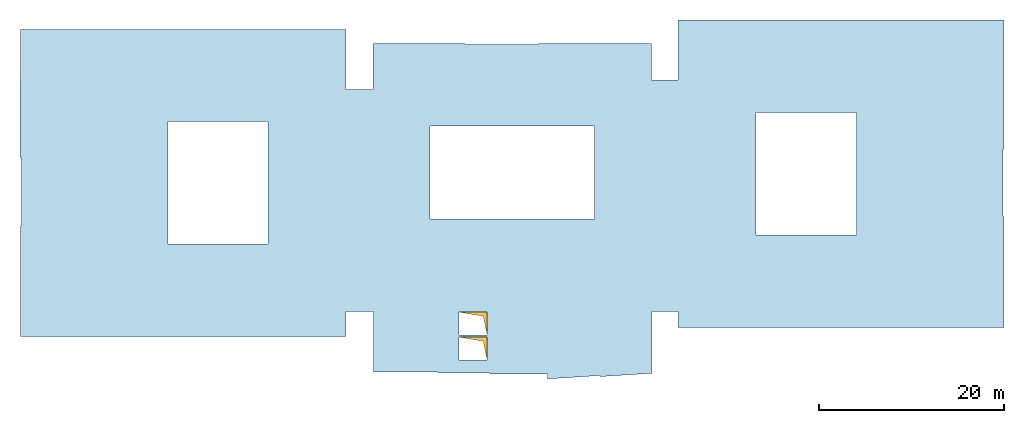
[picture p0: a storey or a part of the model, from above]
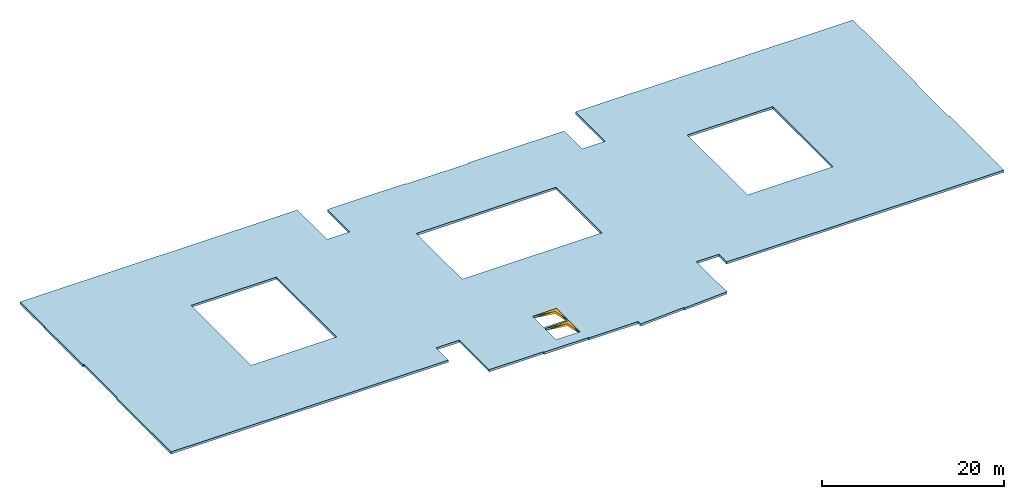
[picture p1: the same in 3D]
Properties of the parts of a building model (IFC4), part 1 of 80

# File
Description: no view
File name: 6-300-WUN-H2-000-000-FMO-V-00#260608.ifc
Time: 2026-06-08T13:22:10
Author: Tschörner Christoph, a|sh
Organization: No Organization
Written by: ODA SDAI 25.4
Authorization: christoph.tschoerner

# IfcProject, 40271-01 Psychiatrie Neubau Wunstorf LPH5
AllplanAttributes - Normalhöhennull: 43.1 m; Projektvorlage: ash_20210624

# IfcSite, Psychiatrie Neubau Wunstorf
RefLatitude: 48, 8, 10, 320000; RefLongitude: 11, 41, 19, 320000; RefElevation: 43.1 m

# IfcBuildingStorey (6)
In: Neubau H2 Stationsgebäude
Name | Elevation (m)
H2 Ebene +4/ Dachebene | 14.5
H2 Ebene +3 | 11.1
H2 Ebene +2 | 7.35
H2 Ebene +1 | 3.6
H2 Ebene 0 | -0.2
H2 Gründung | -3.1

# IfcSpace (512)
AllplanAttributes - Flächenart_Wohnfläche: WO; Raum unter Treppe (Wohnfl erst ab 2m): 0; Faktor_DIN277: 1; Bauteil: H2; Abrechnungsart: m²; Objektname: Raum
Name | In | LongName | Raumumschließung | Flächenart_DIN277 | Nutzungsart_Din277 | Ortscode_Geschoßbezeichnung | Faktor_Wohnfläche_Raum | Raumzone (nach DIN 18599) | ash_lichte Raumhöhe | Raumnr. Bauherr | Raumprogramm Soll (m2) | OKFF | Allright_Bauteil_ID
WUN-H2-E03-A01 | H2 Ebene +3 | A1 | R | N | VF | Ebene 0 | 1 | -- | 16.997207 | VF | 0 | 11.25 | 1265Rau0000000058 | AllplanAttributes - Status: Neubau; BauNVO_Anrechnung_auf_GR: 0; BauNVO_Anrechnung_auf_GF: 0; ash D_Detailverweis: D1502; ash D_Plannummer: D1501; Pset_SpaceCommon - IsExternal: no; HandicapAccessible: no; Pset_SpaceFireSafetyRequirements - FireExit: no; FireRiskFaktor: A; SprinklerProtection: no; Pset_SpaceLightingRequirements - ArtificialLighting: no; Pset_SpaceThermalRequirements - SpaceHumidity: 0; NaturalVentilation: no; AirConditioning: no; SpaceTemperatureMin: 0; SpaceTemperatureMax: 0
WUN-H2-E03-F03 | H2 Ebene +3 | Flur | R | N | VF | Ebene +3 | 1 | Ne | (15096.46-36)/1000- | VF | 0 | 11.25 | 1265Rau0000000012 | AllplanAttributes - Status: Neubau; BauNVO_Anrechnung_auf_GR: 0; BauNVO_Anrechnung_auf_GF: 0; Pset_SpaceCommon - IsExternal: no; HandicapAccessible: no; Pset_SpaceFireSafetyRequirements - FireExit: no; FireRiskFaktor: A; SprinklerProtection: no; Pset_SpaceLightingRequirements - ArtificialLighting: no; Pset_SpaceThermalRequirements - SpaceHumidity: 0; NaturalVentilation: no; AirConditioning: no; SpaceTemperatureMin: 0; SpaceTemperatureMax: 0
WUN-H2-E03-T03 | H2 Ebene +3 | TH 3 | R | N | VF | Ebene +3 | 1 | Ne | (16508.762-36)/1000- | VF | 0 | 11.25 | 1265Rau0000000005 | AllplanAttributes - Status: Neubau; BauNVO_Anrechnung_auf_GR: 0; BauNVO_Anrechnung_auf_GF: 0; ash D_Detailverweis: TRH 3; ash D_Plannummer: D1527; Pset_SpaceCommon - IsExternal: no; HandicapAccessible: no; Pset_SpaceFireSafetyRequirements - FireExit: no; FireRiskFaktor: A; SprinklerProtection: no; Pset_SpaceLightingRequirements - ArtificialLighting: no; Pset_SpaceThermalRequirements - SpaceHumidity: 0; NaturalVentilation: no; AirConditioning: no; SpaceTemperatureMin: 0; SpaceTemperatureMax: 0
WUN-H2-E03-F02 | H2 Ebene +3 | Flur | R | N | VF | Ebene +3 | 1 | Ne | (16487.705-36)/1000- | VF | 0 | 11.25 | 1265Rau0000000023 | AllplanAttributes - Status: Neubau; BauNVO_Anrechnung_auf_GR: 0; BauNVO_Anrechnung_auf_GF: 0; Pset_SpaceCommon - IsExternal: no; HandicapAccessible: no; Pset_SpaceFireSafetyRequirements - FireExit: no; FireRiskFaktor: A; SprinklerProtection: no; Pset_SpaceLightingRequirements - ArtificialLighting: no; Pset_SpaceThermalRequirements - SpaceHumidity: 0; NaturalVentilation: no; AirConditioning: no; SpaceTemperatureMin: 0; SpaceTemperatureMax: 0
WUN-H2-E03-F01 | H2 Ebene +3 | Flur | R | N | VF | Ebene +3 | 1 | Ne | (16879.431-36)/1000- | VF | 0 | 11.25 | 1265Rau0000000034 | AllplanAttributes - Status: Neubau; BauNVO_Anrechnung_auf_GR: 0; BauNVO_Anrechnung_auf_GF: 0; Pset_SpaceCommon - IsExternal: no; HandicapAccessible: no; Pset_SpaceFireSafetyRequirements - FireExit: no; FireRiskFaktor: A; SprinklerProtection: no; Pset_SpaceLightingRequirements - ArtificialLighting: no; Pset_SpaceThermalRequirements - SpaceHumidity: 0; NaturalVentilation: no; AirConditioning: no; SpaceTemperatureMin: 0; SpaceTemperatureMax: 0
WUN-H2-E03-T01 | H2 Ebene +3 | TH 1 | R | N | VF | Ebene 0 | 1 | Ne | (15996.87-36)/1000- | VF | 0 | 11.25 | 1265Rau0000000046 | AllplanAttributes - BauNVO_Anrechnung_auf_GR: 0; BauNVO_Anrechnung_auf_GF: 0; ash D_Detailverweis: TRH 1; ash D_Plannummer: D1525; ash R_Verweis Wandansicht: 1537; Pset_SpaceCommon - IsExternal: no; HandicapAccessible: no; Pset_SpaceFireSafetyRequirements - FireExit: no; FireRiskFaktor: A; SprinklerProtection: no; Pset_SpaceLightingRequirements - ArtificialLighting: no; Pset_SpaceThermalRequirements - SpaceHumidity: 0; NaturalVentilation: no; AirConditioning: no; SpaceTemperatureMin: 0; SpaceTemperatureMax: 0
WUN-H2-E03-S09 | H2 Ebene +3 | Schacht RLT | R | N | NUF | Ebene +3 | 1 |  | 15.428119 | 5.10_01 | 0 | 11.25 | 1266Rau0812597045 | AllplanAttributes - Text1: Schachbreite in LP 5 kleiner; Text4: x
WUN-H2-E03-S02 | H2 Ebene +3 | Schacht RLT | R | N | NUF | Ebene +3 | 1 | -- | 16.487427 | 5.10_01 | 0 | 11.25 | 1266Rau0812596766 | AllplanAttributes - Text1: Schachbreite in LP 5 kleiner; Text4: x
WUN-H2-E03-019a | H2 Ebene +3 | ZBV | R | TF | NUF | Ebene +3 | 1 | Ne | 14.598275 |  | 40 | 11.25 | 1266Rau0812715618
WUN-H2-E03-019a | H2 Ebene +3 | Wäscheraum | R | TF | NUF | Ebene +3 | 1 | Ne | 14.728779 | 4.03_01 | 40 | 11.25 | 1266Rau0812715573 | AllplanAttributes - Text1: neu (vorher Kriechraum wegen Dachneigung)
WUN-H2-E03-011 | H2 Ebene +3 | ZBV | R | B | NUF | Ebene +3 | 1 | Ne | 15.222558 | 4.03_01 | 0 | 11.25 | 1266Rau0000012840
WUN-H2-E03-002 | H2 Ebene +3 | Aufzugstechnik | R | N | NUF | Ebene +3 | 1 | Ne | 16.997207 | 5.10_01 | 0 | 11.25 | 1266Rau0812647188
WUN-H2-E03-S01 | H2 Ebene +3 | Schacht Hausanschluss | R | N | NUF | Ebene +3 | 1 | Ne | 16.999095 | 5.10_01 | 0 | 11.25 | 1266Rau0000012882
WUN-H2-E03-020 | H2 Ebene +3 | ZBV | R | B | NUF | Ebene +3 | 1 | Ne | 15.380686 |  | 0 | 11.25 | 1266Rau0000012867 | AllplanAttributes - Text5: temporär
WUN-H2-E03-017-A | H2 Ebene +3 | Gepäcklager Patienten | R | N | NUF | Ebene +3 | 1 | Ne | 14.523293 | 2.07.01_G1_46 | 20 | 11.25 | 1266Rau0812642456 | AllplanAttributes - BauNVO_Anrechnung_auf_GR: 0; BauNVO_Anrechnung_auf_GF: 0; Pset_SpaceCommon - IsExternal: no; HandicapAccessible: no; Pset_SpaceFireSafetyRequirements - FireExit: no; FireRiskFaktor: A; SprinklerProtection: no; Pset_SpaceLightingRequirements - ArtificialLighting: no; Pset_SpaceThermalRequirements - SpaceHumidity: 0; NaturalVentilation: no; AirConditioning: no; SpaceTemperatureMin: 0; SpaceTemperatureMax: 0
WUN-H2-E03-017-B | H2 Ebene +3 | Gepäcklager Patienten | R | N | NUF | Ebene +3 | 1 | Ne | 14.460387 | 2.07.01_G1_46 | 20 | 11.25 | 1266Rau0000012932
WUN-H2-E03-018 | H2 Ebene +3 | Wärmezentrale | R | TF | NUF | Ebene +3 | 1 | Ne | 14.461808 | SAN | 40 | 11.25 | 1266Rau0000012761
WUN-H2-E03-007 | H2 Ebene +3 | TW-Zentrale |  | TF |  | Ebene +3 | 1 | Ne | 14.624330 | SAN | 20 | 11.25 | 1266Rau0000012780
WUN-H2-E03-013 | H2 Ebene +3 | BMA | R | TF | NUF | Ebene +3 | 1 | Ne | 16.720700 | ELT | 4 | 11.25 | 1266Rau0000012908
WUN-H2-E03-014 | H2 Ebene +3 | AV Zentrale | R | TF | NUF | Ebene +3 | 1 | Ne | 15.596381 | ELT | 40 | 11.25 | 1266Rau0000013429
WUN-H2-E03-004 | H2 Ebene +3 | EDV Zentrale | R | B | NUF | Ebene +3 | 1 | Ne | 14.938808 | 4.03_01 | 0 | 11.25 | 1266Rau0000012799
WUN-H2-E03-016 | H2 Ebene +3 | SV Zentrale | R | TF | NUF | Ebene +3 | 1 | Ne | 15.590158 | ELT | 40 | 11.25 | 1266Rau0000013380
WUN-H2-E03-001 | H2 Ebene +3 | Batterie PV | R | B | NUF | Ebene +3 | 1 | Ne | 15.017221 | 4.03_01 | 0 | 11.25 | 1266Rau0000012806
WUN-H2-E03-002 | H2 Ebene +3 | Vorraum | R | N | NUF | Ebene +3 | 1 | Ne | 16.517341 | 5.10_01 | 0 | 11.25 | 1266Rau0000012858 | AllplanAttributes - Text1: voher Aufzugstechnik
WUN-H2-E03-006 | H2 Ebene +3 | Kältezentrale | R | TF | NUF | Ebene +3 | 1 | Ne | 14.622265 | SAN | 80 | 11.25 | 1266Rau0000012749
WUN-H2-E03-010b | H2 Ebene +3 | DU/WC 1 | R | N | NUF | Ebene +3 | 1 | WC | (15373.888-36)/1000- | 4.03_02 | 8 | 11.25 | 1266Rau0000012955 | AllplanAttributes - ash R_Verweis Wandansicht: 2025; Text3: Sanitärraum
WUN-H2-E03-010a | H2 Ebene +3 | WC | R | N | NUF | Ebene +3 | 1 | WC | (15661.679-36)/1000- | 4.03_02 | 8 | 11.25 | 1266Rau0000015340 | AllplanAttributes - ash R_Verweis Wandansicht: 2025; Text3: Sanitärraum
WUN-H2-E03-009a | H2 Ebene +3 | Beh. DU/WC | R | N | NUF | Ebene +3 | 1 | WC | (16526.15-36)/1000- | 4.03_02 | 8 | 11.25 | 1266Rau0000015356 | AllplanAttributes - ash R_Verweis Wandansicht: 2025; Text3: Sanitärraum
WUN-H2-E03-010c | H2 Ebene +3 | DU/WC 2 | R | N | NUF | Ebene +3 | 1 | WC | (15452.129-36)/1000- | 4.03_02 | 8 | 11.25 | 1266Rau0812666917 | AllplanAttributes - ash R_Verweis Wandansicht: 2025; Text3: Sanitärraum
WUN-H2-E03-008 | H2 Ebene +3 | Lager | R | N | NUF | Ebene +3 | 1 | Ne | (16488.633-36)/1000- | 2.07.01_G1_46 | 20 | 11.25 | 1266Rau0000015419
WUN-H2-E03-010 | H2 Ebene +3 | Umkleide 2 | R | B | NUF | Ebene +3 | 1 | WC | (15849.672-36)/1000- | 4.03_01 | 23 | 11.25 | 1266Rau0000015290 | AllplanAttributes - ash R_Verweis Wandansicht: 2025; Text3: Umkleide
WUN-H2-E03-009 | H2 Ebene +3 | Umkleide 1 | R | B | NUF | Ebene +3 | 1 | WC | (16544.363-36)/1000- | 4.03_01 | 23 | 11.25 | 1266Rau0812598643 | AllplanAttributes - ash R_Verweis Wandansicht: 2025; Text3: Umkleide
WUN-H2-E03-012a | H2 Ebene +3 | Nasszelle Bereitschaft | R | N | NUF | Ebene +3 | 1 | WC | (16775.506-36)/1000- | 2.07.01_G1_46 | 0 | 11.25 | 1266Rau0000015511 | AllplanAttributes - Status: Neubau; ash R_Verweis Wandansicht: 2027
WUN-H2-E03-012 | H2 Ebene +3 | Bereitschaftsdienst | R | N | NUF | Ebene +3 | 1 | So | (16512.865-36)/1000- | 2.07.01_G1_46 | 0 | 11.25 | 1266Rau0000015498 | AllplanAttributes - ash R_Verweis Wandansicht: 2027; Text5: ja
WUN-H2-E03-003 | H2 Ebene +3 | Bettenlager |  |  |  | Ebene +3 | 1 | Ne | (15478.587-36)/1000- | 5.05_01 | 55 | 11.25 | 1266Rau0000012811
WUN-H2-E03-019 | H2 Ebene +3 | PuMi Zentral | R | N | NUF | Ebene +3 | 1 | Ne | (14658.973-36)/1000- | 5.10_01 | 16 | 11.25 | 1266Rau0000015371
WUN-H2-E03-015 | H2 Ebene +3 | TZ RLT 4 - Block 3 | R | TF | NUF | Ebene +3 | 1 | Ne | 14.408729 | RLT/MSR | 250 | 11.25 | 1266Rau0000012920 | AllplanAttributes - ash D_Detailverweis: Kälte.; ash D_Plannummer: D1602
WUN-H2-E03-005 | H2 Ebene +3 | TZ RLT 2 - Block 1 | R | TF | NUF | Ebene +3 | 1 | Ne | 14.593054 | RLT/MSR | 250 | 11.25 | 1266Rau0000012892 | AllplanAttributes - ash D_Detailverweis: Kälte.; ash D_Plannummer: D1603
WUN-H2-E03- | H2 Ebene +3 | Kältemaschine | R | TF | NUF | Ebene +3 | 1 | Ne | 18.500000 |  | 0 | 11.25 | 1266Rau0812698243 | AllplanAttributes - ash D_Detailverweis: Kälte.; ash D_Plannummer: D1601; ash R_Verweis Wandansicht: 1606
WUN-H2-E02-F03 | H2 Ebene +2 | Flur | R | N | VF | Ebene +2 | 1 | Ne | 10.600000 | VF | 0 | 7.5 | 1215Rau0000006920 | AllplanAttributes - Status: Neubau; BauNVO_Anrechnung_auf_GR: 0; BauNVO_Anrechnung_auf_GF: 0; Pset_SpaceCommon - IsExternal: no; HandicapAccessible: no; Pset_SpaceFireSafetyRequirements - FireExit: no; FireRiskFaktor: A; SprinklerProtection: no; Pset_SpaceLightingRequirements - ArtificialLighting: no; Pset_SpaceThermalRequirements - SpaceHumidity: 0; NaturalVentilation: no; AirConditioning: no; SpaceTemperatureMin: 0; SpaceTemperatureMax: 0
WUN-H2-E02-F07 | H2 Ebene +2 | Flur | R | N | VF | Ebene +2 | 1 | Ne | 10.600000 | VF | 0 | 7.5 | 1215Rau0000006941 | AllplanAttributes - Status: Neubau; BauNVO_Anrechnung_auf_GR: 0; BauNVO_Anrechnung_auf_GF: 0; Pset_SpaceCommon - IsExternal: no; HandicapAccessible: no; Pset_SpaceFireSafetyRequirements - FireExit: no; FireRiskFaktor: A; SprinklerProtection: no; Pset_SpaceLightingRequirements - ArtificialLighting: no; Pset_SpaceThermalRequirements - SpaceHumidity: 0; NaturalVentilation: no; AirConditioning: no; SpaceTemperatureMin: 0; SpaceTemperatureMax: 0
WUN-H2-E02-T01 | H2 Ebene +2 | TH 1 | R | N | VF | Ebene +2 | 1 | Ne | 10.900000 | VF | 0 | 7.5 | 1215Rau0000006911 | AllplanAttributes - BauNVO_Anrechnung_auf_GR: 0; BauNVO_Anrechnung_auf_GF: 0; ash D_Detailverweis: TRH 1; ash D_Plannummer: D1525; ash R_Verweis Wandansicht: 1537; Pset_SpaceCommon - IsExternal: no; HandicapAccessible: no; Pset_SpaceFireSafetyRequirements - FireExit: no; FireRiskFaktor: A; SprinklerProtection: no; Pset_SpaceLightingRequirements - ArtificialLighting: no; Pset_SpaceThermalRequirements - SpaceHumidity: 0; NaturalVentilation: no; AirConditioning: no; SpaceTemperatureMin: 0; SpaceTemperatureMax: 0
WUN-H2-E02-F02 | H2 Ebene +2 | Flur | R | N | VF | Ebene +2 | 1 | Ne | 10.600000 | VF | 0 | 7.5 | 1215Rau0000006938 | AllplanAttributes - Status: Neubau; BauNVO_Anrechnung_auf_GR: 0; BauNVO_Anrechnung_auf_GF: 0; Pset_SpaceCommon - IsExternal: no; HandicapAccessible: no; Pset_SpaceFireSafetyRequirements - FireExit: no; FireRiskFaktor: A; SprinklerProtection: no; Pset_SpaceLightingRequirements - ArtificialLighting: no; Pset_SpaceThermalRequirements - SpaceHumidity: 0; NaturalVentilation: no; AirConditioning: no; SpaceTemperatureMin: 0; SpaceTemperatureMax: 0
WUN-H2-E02-F05 | H2 Ebene +2 | Flur | R | N | VF | Ebene +2 | 1 | Ne | (11571.197-36)/1000- | VF | 0 | 7.5 | 1215Rau0000006929 | AllplanAttributes - Status: Neubau; BauNVO_Anrechnung_auf_GR: 0; BauNVO_Anrechnung_auf_GF: 0; Pset_SpaceCommon - IsExternal: no; HandicapAccessible: no; Pset_SpaceFireSafetyRequirements - FireExit: no; FireRiskFaktor: A; SprinklerProtection: no; Pset_SpaceLightingRequirements - ArtificialLighting: no; Pset_SpaceThermalRequirements - SpaceHumidity: 0; NaturalVentilation: no; AirConditioning: no; SpaceTemperatureMin: 0; SpaceTemperatureMax: 0
WUN-H2-E02-F06 | H2 Ebene +2 | Flur | R | N | VF | Ebene +2 | 1 | Ne | (12265.514-36)/1000- | VF | 0 | 7.5 | 1215Rau0000006899 | AllplanAttributes - Status: Neubau; BauNVO_Anrechnung_auf_GR: 0; BauNVO_Anrechnung_auf_GF: 0; ash R_Verweis Wandansicht: 2005; Pset_SpaceCommon - IsExternal: no; HandicapAccessible: no; Pset_SpaceFireSafetyRequirements - FireExit: no; FireRiskFaktor: A; SprinklerProtection: no; Pset_SpaceLightingRequirements - ArtificialLighting: no; Pset_SpaceThermalRequirements - SpaceHumidity: 0; NaturalVentilation: no; AirConditioning: no; SpaceTemperatureMin: 0; SpaceTemperatureMax: 0
WUN-H2-E02-F04 | H2 Ebene +2 | Flur | R | N | VF | Ebene +2 | 1 | Ne | (12291.454-36)/1000- | VF | 0 | 7.5 | 1215Rau0000006926 | AllplanAttributes - Status: Neubau; BauNVO_Anrechnung_auf_GR: 0; BauNVO_Anrechnung_auf_GF: 0; Pset_SpaceCommon - IsExternal: no; HandicapAccessible: no; Pset_SpaceFireSafetyRequirements - FireExit: no; FireRiskFaktor: A; SprinklerProtection: no; Pset_SpaceLightingRequirements - ArtificialLighting: no; Pset_SpaceThermalRequirements - SpaceHumidity: 0; NaturalVentilation: no; AirConditioning: no; SpaceTemperatureMin: 0; SpaceTemperatureMax: 0
WUN-H2-E02-F11 | H2 Ebene +2 | Flur | R | N | VF | Ebene +2 | 1 | Ne | (12286.577-36)/1000- | VF | 0 | 7.5 | 1215Rau0000006893 | AllplanAttributes - BauNVO_Anrechnung_auf_GR: 0; BauNVO_Anrechnung_auf_GF: 0; Pset_SpaceCommon - IsExternal: no; HandicapAccessible: no; Pset_SpaceFireSafetyRequirements - FireExit: no; FireRiskFaktor: A; SprinklerProtection: no; Pset_SpaceLightingRequirements - ArtificialLighting: no; Pset_SpaceThermalRequirements - SpaceHumidity: 0; NaturalVentilation: no; AirConditioning: no; SpaceTemperatureMin: 0; SpaceTemperatureMax: 0
WUN-H2-E02-F10 | H2 Ebene +2 | Flur | R | N | VF | Ebene +2 | 1 | Ne | (11570.89-36)/1000- | VF | 0 | 7.5 | 1215Rau0000006932 | AllplanAttributes - Status: Neubau; BauNVO_Anrechnung_auf_GR: 0; BauNVO_Anrechnung_auf_GF: 0; Pset_SpaceCommon - IsExternal: no; HandicapAccessible: no; Pset_SpaceFireSafetyRequirements - FireExit: no; FireRiskFaktor: A; SprinklerProtection: no; Pset_SpaceLightingRequirements - ArtificialLighting: no; Pset_SpaceThermalRequirements - SpaceHumidity: 0; NaturalVentilation: no; AirConditioning: no; SpaceTemperatureMin: 0; SpaceTemperatureMax: 0
WUN-H2-E02-F09 | H2 Ebene +2 | Flur | R | N | VF | Ebene +2 | 1 | Ne | (12263.81-36)/1000- | VF | 0 | 7.5 | 1215Rau0000006914 | AllplanAttributes - BauNVO_Anrechnung_auf_GR: 0; BauNVO_Anrechnung_auf_GF: 0; Pset_SpaceCommon - IsExternal: no; HandicapAccessible: no; Pset_SpaceFireSafetyRequirements - FireExit: no; FireRiskFaktor: A; SprinklerProtection: no; Pset_SpaceLightingRequirements - ArtificialLighting: no; Pset_SpaceThermalRequirements - SpaceHumidity: 0; NaturalVentilation: no; AirConditioning: no; SpaceTemperatureMin: 0; SpaceTemperatureMax: 0
WUN-H2-E02-F01 | H2 Ebene +2 | Foyer | R | N | VF | Ebene +2 | 1 | Ne | 10.250000 | VF | 0 | 7.5 | 1215Rau0000006896 | AllplanAttributes - Status: Neubau; BauNVO_Anrechnung_auf_GR: 0; BauNVO_Anrechnung_auf_GF: 0; Pset_SpaceCommon - IsExternal: no; HandicapAccessible: no; Pset_SpaceFireSafetyRequirements - FireExit: no; FireRiskFaktor: A; SprinklerProtection: no; Pset_SpaceLightingRequirements - ArtificialLighting: no; Pset_SpaceThermalRequirements - SpaceHumidity: 0; NaturalVentilation: no; AirConditioning: no; SpaceTemperatureMin: 0; SpaceTemperatureMax: 0
WUN-H2-E02-F08 | H2 Ebene +2 | Flur | R | N | VF | Ebene +2 | 1 | Ne | 10.900000 | VF | 0 | 7.5 | 1215Rau0000006905 | AllplanAttributes - Status: Neubau; BauNVO_Anrechnung_auf_GR: 0; BauNVO_Anrechnung_auf_GF: 0; Pset_SpaceCommon - IsExternal: no; HandicapAccessible: no; Pset_SpaceFireSafetyRequirements - FireExit: no; FireRiskFaktor: A; SprinklerProtection: no; Pset_SpaceLightingRequirements - ArtificialLighting: no; Pset_SpaceThermalRequirements - SpaceHumidity: 0; NaturalVentilation: no; AirConditioning: no; SpaceTemperatureMin: 0; SpaceTemperatureMax: 0
WUN-H2-E02-A02 | H2 Ebene +2 | A1 | R | N | VF | Ebene +2 | 1 | -- | 10.900000 | VF | 0 | 7.5 | 1215Rau0000006935 | AllplanAttributes - Status: Neubau; BauNVO_Anrechnung_auf_GR: 0; BauNVO_Anrechnung_auf_GF: 0; ash D_Detailverweis: D1502; ash D_Plannummer: D1501; Pset_SpaceCommon - IsExternal: no; HandicapAccessible: no; Pset_SpaceFireSafetyRequirements - FireExit: no; FireRiskFaktor: A; SprinklerProtection: no; Pset_SpaceLightingRequirements - ArtificialLighting: no; Pset_SpaceThermalRequirements - SpaceHumidity: 0; NaturalVentilation: no; AirConditioning: no; SpaceTemperatureMin: 0; SpaceTemperatureMax: 0
WUN-H2-E02-A01 | H2 Ebene +2 | A2 | R | N | VF | Ebene +2 | 1 | -- | 10.900000 | VF | 0 | 7.5 | 1215Rau0000006902 | AllplanAttributes - Status: Neubau; BauNVO_Anrechnung_auf_GR: 0; BauNVO_Anrechnung_auf_GF: 0; ash D_Detailverweis: D1502; ash D_Plannummer: D1501; Pset_SpaceCommon - IsExternal: no; HandicapAccessible: no; Pset_SpaceFireSafetyRequirements - FireExit: no; FireRiskFaktor: A; SprinklerProtection: no; Pset_SpaceLightingRequirements - ArtificialLighting: no; Pset_SpaceThermalRequirements - SpaceHumidity: 0; NaturalVentilation: no; AirConditioning: no; SpaceTemperatureMin: 0; SpaceTemperatureMax: 0
WUN-H2-E02-T03 | H2 Ebene +2 | TH 3 | R | N | VF | Ebene +2 | 1 | Ne | 10.900000 | VF | 0 | 7.5 | 1215Rau0000006923 | AllplanAttributes - Status: Neubau; BauNVO_Anrechnung_auf_GR: 0; BauNVO_Anrechnung_auf_GF: 0; ash D_Detailverweis: TRH 3; ash D_Plannummer: D1527; Pset_SpaceCommon - IsExternal: no; HandicapAccessible: no; Pset_SpaceFireSafetyRequirements - FireExit: no; FireRiskFaktor: A; SprinklerProtection: no; Pset_SpaceLightingRequirements - ArtificialLighting: no; Pset_SpaceThermalRequirements - SpaceHumidity: 0; NaturalVentilation: no; AirConditioning: no; SpaceTemperatureMin: 0; SpaceTemperatureMax: 0
WUN-H2-E02-T04 | H2 Ebene +2 | TH 4 | R | N | VF | Ebene +2 | 1 | Ne | (11033.412-36)/1000- | VF | 0 | 7.5 | 1215Rau0000006908 | AllplanAttributes - Status: Neubau; BauNVO_Anrechnung_auf_GR: 0; BauNVO_Anrechnung_auf_GF: 0; ash D_Detailverweis: TRH 4; ash D_Plannummer: D1528; Pset_SpaceCommon - IsExternal: no; HandicapAccessible: no; Pset_SpaceFireSafetyRequirements - FireExit: no; FireRiskFaktor: A; SprinklerProtection: no; Pset_SpaceLightingRequirements - ArtificialLighting: no; Pset_SpaceThermalRequirements - SpaceHumidity: 0; NaturalVentilation: no; AirConditioning: no; SpaceTemperatureMin: 0; SpaceTemperatureMax: 0
WUN-H2-E02-T02 | H2 Ebene +2 | TH 2 | R | N | VF | Ebene +2 | 1 | Ne | (11031.571-36)/1000- | VF | 0 | 7.5 | 1215Rau0000006917 | AllplanAttributes - Status: Neubau; BauNVO_Anrechnung_auf_GR: 0; BauNVO_Anrechnung_auf_GF: 0; ash D_Detailverweis: TRH 2; ash D_Plannummer: D1526; ash R_Verweis Wandansicht: 1538; Text1: Detail TRH-Wand/-Decke Anschluss Holztafelbauweise; Text4: x; Pset_SpaceCommon - IsExternal: no; HandicapAccessible: no; Pset_SpaceFireSafetyRequirements - FireExit: no; FireRiskFaktor: A; SprinklerProtection: no; Pset_SpaceLightingRequirements - ArtificialLighting: no; Pset_SpaceThermalRequirements - SpaceHumidity: 0; NaturalVentilation: no; AirConditioning: no; SpaceTemperatureMin: 0; SpaceTemperatureMax: 0
WUN-H2-E02-008 | H2 Ebene +2 | Speiseraum | R | N | NUF | Ebene +2 | 1 | So | 10.600000 | 2.07.01_G1_30 | 42 | 7.5 | 1216Rau0000046485 | AllplanAttributes - ash R_Verweis Wandansicht: 2019; Text1: Anpassung Flucht Traufe Achse I 3.1-3.5; Text4: x
WUN-H2-E02-050 | H2 Ebene +2 | Stationsküche | R | N | NUF | Ebene +2 | 1 | So | 10.600000 | 2.07.01_A2_36 | 16 | 7.5 | 1216Rau0000047223
WUN-H2-E02-L02 | H2 Ebene +2 | Loggia II | S | N | NUF | Ebene +2 | 1 | So | (10820-180+45)/1000- |  | 0 | 7.5 | 1216Rau0812993788 | AllplanAttributes - ash D_Detailverweis: Außen; ash D_Plannummer: D1555
WUN-H2-E02-L01 | H2 Ebene +2 | Loggia I | S | N | NUF | Ebene +2 | 1 | So | (10820-180+45)/1000- |  | 0 | 7.5 | 1216Rau0812993813 | AllplanAttributes - ash D_Detailverweis: Außen; ash D_Plannummer: D1556
WUN-H2-E02-048 | H2 Ebene +2 | Stationsküche | R | N | NUF | Ebene +2 | 1 | So | 10.600000 | 2.07.01_G1_36 | 16 | 7.5 | 1216Rau0000046499 | AllplanAttributes - ash R_Verweis Wandansicht: 2008
WUN-H2-E02-055 | H2 Ebene +2 | Speiseraum | R | N | NUF | Ebene +2 | 1 | So | 10.600000 | 2.07.01_A2_30 | 42 | 7.5 | 1216Rau0000047209 | AllplanAttributes - Text1: Anpassung Flucht Traufe Achse O 3.1-3.5; Text4: x
WUN-H2-E02-060 | H2 Ebene +2 | Aufenthalt / Besucher |  |  |  | Ebene +2 | 1 | So | 10.600000 | 2.07.01_A2_32 | 16 | 7.5 | 1216Rau0000046781
WUN-H2-E02-061 | H2 Ebene +2 | DR Therapeut | R | N | NUF | Ebene +2 | 1 | Bü | 10.600000 | 01.12.02_A2_05 | 16 | 7.5 | 1216Rau0000046767 | AllplanAttributes - ash R_Verweis Wandansicht: 2028
WUN-H2-E02-003 | H2 Ebene +2 | Aufenthalt / Besucher | R | N | NUF | Ebene +2 | 1 | So | 10.600000 | 2.07.01_G1_32 | 16 | 7.5 | 1216Rau0000046703 | AllplanAttributes - ash R_Verweis Wandansicht: 2026
WUN-H2-E02-041 | H2 Ebene +2 | Ruheraum | R | N | NUF | Ebene +2 | 1 | Be | (11009.893-36)/1000- | 2.11_G1_01 | 25 | 7.5 | 1216Rau0812778629
WUN-H2-E02-038 | H2 Ebene +2 | AR unrein | R | N | NUF | Ebene +2 | 1 | So | (11408.909-36)/1000- | 2.07.01_G1_41 | 6 | 7.5 | 1216Rau0000046059 | AllplanAttributes - ash R_Verweis Wandansicht: 2020; Text5: temporär
WUN-H2-E02-030 | H2 Ebene +2 | WC Pers. | R | N | NUF | Ebene +2 | 1 | WC | (11296.826-36)/1000- | 2.07.01_G1_56 | 3.5 | 7.5 | 1216Rau0000046151 | AllplanAttributes - Text3: Sanitärraum
WUN-H2-E02-031 | H2 Ebene +2 | WC Pers. | R | N | NUF | Ebene +2 | 1 | WC | (11296.826-36)/1000- | 2.07.01_G1_57 | 3.5 | 7.5 | 1216Rau0000046139 | AllplanAttributes - Text3: Sanitärraum
WUN-H2-E02-026 | H2 Ebene +2 | Lager Fixierbett |  |  |  | Ebene +2 | 1 | Ne | (10961.888-36)/1000- | 2.07.01_G1_34 | 4 | 7.5 | 1216Rau0000046175
WUN-H2-E02-040 | H2 Ebene +2 | Geräte |  |  |  | Ebene +2 | 1 | Ne | (10974.699-36)/1000- | 2.07.01_G1_45 | 20 | 7.5 | 1216Rau0000046035
WUN-H2-E02-029 | H2 Ebene +2 | EDV | R | TF | NUF | Ebene +2 | 1 | Ne | (11281.294-36)/1000- | ELT | 7.5 | 7.5 | 1216Rau0000046163
WUN-H2-E02-032 | H2 Ebene +2 | Wäsche rein | R | N | NUF | Ebene +2 | 1 | Ne | (11412.619-36)/1000- | 2.07.01_G1_42 | 8 | 7.5 | 1216Rau0000046071
WUN-H2-E02-039 | H2 Ebene +2 | Stationsbad | R | N | NUF | Ebene +2 | 1 | WC | (11196.639-36)/1000- | 2.07.01_G1_40 | 16 | 7.5 | 1216Rau0000046047 | AllplanAttributes - ash R_Verweis Wandansicht: 2023
WUN-H2-E02-035 | H2 Ebene +2 | Pause Personal | R | N | NUF | Ebene +2 | 1 | So | (11948.949-36)/1000- | 2.07.01_G1_58 | 14 | 7.5 | 1216Rau0000047619 | AllplanAttributes - ash R_Verweis Wandansicht: 2012; Text1: Standardvorgaben Ausstattung nicht erfüllt; Text4: x; Text5: ja; Text3: Pausenraum
WUN-H2-E02-034 | H2 Ebene +2 | Sprechzimmer |  |  |  | Ebene +2 | 1 | Bü | (11943.471-36)/1000- | 2.07.01_G1_50 | 16 | 7.5 | 1216Rau0000046097 | AllplanAttributes - Text5: ja
WUN-H2-E02-036 | H2 Ebene +2 | Sprechzimmer |  |  |  | Ebene +2 | 1 | Bü | (11943.471-36)/1000- | 2.07.01_G1_51 | 16 | 7.5 | 1216Rau0000046111 | AllplanAttributes - Text5: ja
WUN-H2-E02-033 | H2 Ebene +2 | Sprechzimmer | R | N | NUF | Ebene +2 | 1 | Bü | (11943.471-36)/1000- | 2.07.01_G1_52 | 16 | 7.5 | 1216Rau0000046083 | AllplanAttributes - ash R_Verweis Wandansicht: 2010; Text5: ja
WUN-H2-E02-037 | H2 Ebene +2 | Sprechzimmer | R | N | NUF | Ebene +2 | 1 | Bü | (11938.051-36)/1000- | 2.07.01_G1_53 | 16 | 7.5 | 1216Rau0000046125 | AllplanAttributes - Text5: ja
WUN-H2-E02-043 | H2 Ebene +2 | Rollstuhlgerechtes Doppelzimmer | R | N | NUF | Ebene +2 | 1 | Be | (11905.104-36)/1000- | 2.07.01_G1_12 | 26 | 7.5 | 1216Rau0000045905 | AllplanAttributes - ash R_Verweis Wandansicht: 2024
WUN-H2-E02-042 | H2 Ebene +2 | Ruheraum | R | N | NUF | Ebene +2 | 1 | Be | (11493.617-36)/1000- | 2.11_G1_02 | 25 | 7.5 | 1216Rau0000045891 | AllplanAttributes - ash R_Verweis Wandansicht: 2003
WUN-H2-E02-045 | H2 Ebene +2 | Doppelzimmer | R | N | NUF | Ebene +2 | 1 | Be | (12754.034-36)/1000- | 2.07.01_G1_19 | 26 | 7.5 | 1216Rau0000045957 | AllplanAttributes - ash R_Verweis Wandansicht: 2001
WUN-H2-E02-044 | H2 Ebene +2 | Einzelzimmer | R | N | NUF | Ebene +2 | 1 | Be | (12399.951-36)/1000- | 2.07.01_G1_07 | 20 | 7.5 | 1216Rau0000045943 | AllplanAttributes - ash R_Verweis Wandansicht: 2002
WUN-H2-E02-047 | H2 Ebene +2 | Einzelzimmer Adipositas | R | N | NUF | Ebene +2 | 1 | Be | (12363.175-36)/1000- | 2.07.01_G1_05 | 20 | 7.5 | 1216Rau0000046009 | AllplanAttributes - ash R_Verweis Wandansicht: 2004
WUN-H2-E02-046 | H2 Ebene +2 | Einzelzimmer mit Zustelloption |  |  |  | Ebene +2 | 1 | Be | (13243.769-36)/1000- | 2.07.01_G1_01 | 25 | 7.5 | 1216Rau0000045995
WUN-H2-E02-042a | H2 Ebene +2 | Bad mit Dusche | R | N | NUF | Ebene +2 | 1 | WC | (11345-36)/1000- | 2.11_G1_04 | 4 | 7.5 | 1216Rau0000045879 | AllplanAttributes - ash R_Verweis Wandansicht: 2003
WUN-H2-E02-041a | H2 Ebene +2 | Bad mit Dusche |  |  |  | Ebene +2 | 1 | WC | (11152.481-36)/1000- | 2.11_G1_03 | 4 | 7.5 | 1216Rau0000045867
WUN-H2-E02-044a | H2 Ebene +2 | Nasszelle EZ | R | N | NUF | Ebene +2 | 1 | WC | (12285.716-36)/1000- | 2.07.01_G1_10 | 4 | 7.5 | 1216Rau0000045931 | AllplanAttributes - ash R_Verweis Wandansicht: 2002
WUN-H2-E02-043a | H2 Ebene +2 | Nasszelle rsg. | R | N | NUF | Ebene +2 | 1 | WC | (12054.913-36)/1000- | 2.07.01_G1_14 | 6 | 7.5 | 1216Rau0000045919 | AllplanAttributes - ash R_Verweis Wandansicht: 2024
WUN-H2-E02-045a | H2 Ebene +2 | Nasszelle DZ | R | N | NUF | Ebene +2 | 1 | WC | (12902.651-36)/1000- | 2.07.01_G1_24 | 4 | 7.5 | 1216Rau0000045971 | AllplanAttributes - ash R_Verweis Wandansicht: 2001
WUN-H2-E02-046a | H2 Ebene +2 | Nasszelle EZ+ |  |  |  | Ebene +2 | 1 | WC | (13095.17-36)/1000- | 2.07.01_G1_03 | 4 | 7.5 | 1216Rau0000045983
WUN-H2-E02-047a | H2 Ebene +2 | Nasszelle EZ | R | N | NUF | Ebene +2 | 1 | WC | (12093.083-36)/1000- | 2.07.01_G1_08 | 4 | 7.5 | 1216Rau0000046023 | AllplanAttributes - ash R_Verweis Wandansicht: 2004
WUN-H2-E02-019 | H2 Ebene +2 | Einzelzimmer mit Zustelloption | R | N | NUF | Ebene +2 | 1 | Be | (12355.284-36)/1000- | 2.07.01_G1_05 | 25 | 7.5 | 1216Rau0000046367
WUN-H2-E02-024 | H2 Ebene +2 | Doppelzimmer |  |  |  | Ebene +2 | 1 | Be | (11493.627-36)/1000- | 2.07.01_G1_17 | 26 | 7.5 | 1216Rau0000046237
WUN-H2-E02-023 | H2 Ebene +2 | Rollstuhlgerechtes Doppelzimmer | R | N | NUF | Ebene +2 | 1 | Be | (11905.092-36)/1000- | 2.07.01_G1_11 | 26 | 7.5 | 1216Rau0000046263
WUN-H2-E02-022 | H2 Ebene +2 | Einzelzimmer | R | N | NUF | Ebene +2 | 1 | Be | (12399.96-36)/1000- | 2.07.01_G1_06 | 20 | 7.5 | 1216Rau0000046301
WUN-H2-E02-021 | H2 Ebene +2 | Doppelzimmer |  |  |  | Ebene +2 | 1 | Be | (12754.025-36)/1000- | 2.07.01_G1_16 | 26 | 7.5 | 1216Rau0000046315
WUN-H2-E02-020 | H2 Ebene +2 | Doppelzimmer | R | B | NUF | Ebene +2 | 1 | Be | (13243.778-36)/1000- | 2.07.01_G1_15 | 26 | 7.5 | 1216Rau0000046353
WUN-H2-E02-019a | H2 Ebene +2 | Nasszelle EZ+ |  |  |  | Ebene +2 | 1 | WC | (11974.225-36)/1000- | 2.07.01_G1_04 | 4 | 7.5 | 1216Rau0000046381
WUN-H2-E02-025a | H2 Ebene +2 | Nasszelle DZ |  |  |  | Ebene +2 | 1 | WC | (11152.481-36)/1000- | 2.07.01_G1_20 | 4 | 7.5 | 1216Rau0000046225
WUN-H2-E02-024a | H2 Ebene +2 | Nasszelle DZ |  |  |  | Ebene +2 | 1 | WC | (11345-36)/1000- | 2.07.01_G1_23 | 4 | 7.5 | 1216Rau0000046251
WUN-H2-E02-023a | H2 Ebene +2 | Nasszelle rsg. | R | N | NUF | Ebene +2 | 1 | WC | (12054.913-36)/1000- | 2.07.01_G1_13 | 6 | 7.5 | 1216Rau0000046277
WUN-H2-E02-022a | H2 Ebene +2 | Nasszelle EZ | R | N | NUF | Ebene +2 | 1 | WC | (12285.716-36)/1000- | 2.07.01_G1_09 | 4 | 7.5 | 1216Rau0000046289
WUN-H2-E02-021a | H2 Ebene +2 | Nasszelle DZ |  |  |  | Ebene +2 | 1 | WC | (12902.651-36)/1000- | 2.07.01_G1_22 | 4 | 7.5 | 1216Rau0000046329
WUN-H2-E02-020a | H2 Ebene +2 | Nasszelle DZ |  |  |  | Ebene +2 | 1 | WC | (13095.17-36)/1000- | 2.07.01_G1_21 | 4 | 7.5 | 1216Rau0000046341
WUN-H2-E02-082 | H2 Ebene +2 | Sprechzimmer |  |  |  | Ebene +2 | 1 | Bü | (11938.052-36)/1000- | 2.07.01_A2_53 | 16 | 7.5 | 1216Rau0000047485 | AllplanAttributes - Text5: ja
WUN-H2-E02-085 | H2 Ebene +2 | Sprechzimmer |  |  |  | Ebene +2 | 1 | Bü | (11943.471-36)/1000- | 2.07.01_A2_50 | 16 | 7.5 | 1216Rau0000047457 | AllplanAttributes - Text5: ja
WUN-H2-E02-084 | H2 Ebene +2 | Pause Personal | R | N | NUF | Ebene +2 | 1 | So | (11948.939-36)/1000- | 2.07.01_A2_58 | 14 | 7.5 | 1216Rau0000047633 | AllplanAttributes - Text1: Standardvorgaben Ausstattung nicht erfüllt; Text4: x; Text5: ja; Text3: Pausenraum
WUN-H2-E02-086 | H2 Ebene +2 | Sprechzimmer |  |  |  | Ebene +2 | 1 | Bü | (11943.5-36)/1000- | 2.07.01_A2_52 | 16 | 7.5 | 1216Rau0000047443 | AllplanAttributes - Text5: ja
WUN-H2-E02-083 | H2 Ebene +2 | Sprechzimmer | R | N | NUF | Ebene +2 | 1 | Bü | (11943.471-36)/1000- | 2.07.01_A2_51 | 16 | 7.5 | 1216Rau0000047471 | AllplanAttributes - Text5: ja
WUN-H2-E02-068 | H2 Ebene +2 | Einzelzimmer Adipositas | R | N | NUF | Ebene +2 | 1 | Be | (12362.92-36)/1000- | 2.07.01_A2_07 | 20 | 7.5 | 1216Rau0000047273
WUN-H2-E02-074 | H2 Ebene +2 | Ruheraum | R | N | NUF | Ebene +2 | 1 | Be | (11006.559-36)/1000- | 2.11_A2_02 | 25 | 7.5 | 1216Rau0000047417 | AllplanAttributes - Text1: Achtung Wand in LP 5 in Achse um 2,5cm nach rechts verschieben!!!; Text4: x
WUN-H2-E02-073 | H2 Ebene +2 | Ruheraum |  |  |  | Ebene +2 | 1 | Be | (11493.779-36)/1000- | 2.11_A2_01 | 25 | 7.5 | 1216Rau0000047391
WUN-H2-E02-070 | H2 Ebene +2 | Doppelzimmer | R | N | NUF | Ebene +2 | 1 | Be | (12753.872-36)/1000- | 2.07.01_A2_15 | 26 | 7.5 | 1216Rau0000047313 | AllplanAttributes - Text1: Achtung Wand in LP 5 in Achse um 2,5cm nach links verschieben!!!; Text4: x
WUN-H2-E02-072 | H2 Ebene +2 | Rollstuhlgerechtes Doppelzimmer |  |  |  | Ebene +2 | 1 | Be | (11905.104-36)/1000- | 2.07.01_A2_11 | 26 | 7.5 | 1216Rau0000047365
WUN-H2-E02-071 | H2 Ebene +2 | Einzelzimmer |  |  |  | Ebene +2 | 1 | Be | (12399.951-36)/1000- | 2.07.01_A2_05 | 20 | 7.5 | 1216Rau0000047339
WUN-H2-E02-069 | H2 Ebene +2 | Einzelzimmer mit Zustelloption | R | N | NUF | Ebene +2 | 1 | Be | (13243.602-36)/1000- | 2.07.01_A2_01 | 25 | 7.5 | 1216Rau0000047287 | AllplanAttributes - Text1: Achtung Wand in LP 5 in Achse um 2,5cm nach links verschieben!!!; Text4: x
WUN-H2-E02-068a | H2 Ebene +2 | Nasszelle EZ | R | N | NUF | Ebene +2 | 1 | WC | (12092.853-36)/1000- | 2.07.01_A2_10 | 4 | 7.5 | 1216Rau0000047261
WUN-H2-E02-069a | H2 Ebene +2 | Nasszelle EZ+ |  |  |  | Ebene +2 | 1 | WC | (13092.982-36)/1000- | 2.07.01_A2_03 | 4 | 7.5 | 1216Rau0000047301
WUN-H2-E02-070a | H2 Ebene +2 | Nasszelle DZ |  |  |  | Ebene +2 | 1 | WC | (12900.464-36)/1000- | 2.07.01_A2_20 | 4 | 7.5 | 1216Rau0000047327
WUN-H2-E02-071a | H2 Ebene +2 | Nasszelle EZ |  |  |  | Ebene +2 | 1 | WC | (12285.716-36)/1000- | 2.07.01_A2_08 | 4 | 7.5 | 1216Rau0000047353
WUN-H2-E02-072a | H2 Ebene +2 | Nasszelle rsg. |  |  |  | Ebene +2 | 1 | WC | (12054.913-36)/1000- | 2.07.01_A2_13 | 6 | 7.5 | 1216Rau0000047379
WUN-H2-E02-073a | H2 Ebene +2 | Bad mit Dusche |  |  |  | Ebene +2 | 1 | WC | (11347.188-36)/1000- | 2.11_A2_03 | 4 | 7.5 | 1216Rau0000047405
WUN-H2-E02-074a | H2 Ebene +2 | Bad mit Dusche |  |  |  | Ebene +2 | 1 | WC | (11154.669-36)/1000- | 2.11_A2_04 | 4 | 7.5 | 1216Rau0000047431
WUN-H2-E02-075 | H2 Ebene +2 | Geräte | R | N | NUF | Ebene +2 | 1 | Ne | (10953.399-36)/1000- | 2.07.01_A2_45 | 20 | 7.5 | 1216Rau0000047523
WUN-H2-E02-078 | H2 Ebene +2 | Wäsche rein |  |  |  | Ebene +2 | 1 | Ne | (11411.94-36)/1000- | 2.07.01_A2_42 | 8 | 7.5 | 1216Rau0000047535
WUN-H2-E02-079 | H2 Ebene +2 | WC Pers. | R | N | NUF | Ebene +2 | 1 | WC | (11296.827-36)/1000- | 2.07.01_A2_56 | 3.5 | 7.5 | 1216Rau0000047547 | AllplanAttributes - Text3: Sanitärraum
WUN-H2-E02-080 | H2 Ebene +2 | WC Pers. | R | N | NUF | Ebene +2 | 1 | WC | (11296.827-36)/1000- | 2.07.01_A2_57 | 3.5 | 7.5 | 1216Rau0000047559 | AllplanAttributes - Text3: Sanitärraum
WUN-H2-E02-081 | H2 Ebene +2 | EDV | R | TF | NUF | Ebene +2 | 1 | Ne | (11281.294-36)/1000- | ELT | 7.5 | 7.5 | 1216Rau0000047571
WUN-H2-E02-077 | H2 Ebene +2 | AR unrein |  |  |  | Ebene +2 | 1 | So | (11407.141-36)/1000- | 2.07.01_A2_40 | 6 | 7.5 | 1216Rau0000047499 | AllplanAttributes - Text5: temporär
WUN-H2-E02-076 | H2 Ebene +2 | Entspannungsbad | R | N | NUF | Ebene +2 | 1 | WC | (11194.88-36)/1000- | 2.07.01_A2_41 | 16 | 7.5 | 1216Rau0000047511 | AllplanAttributes - ash R_Verweis Wandansicht: 2021
WUN-H2-E02-089 | H2 Ebene +2 | Lager Fixierbett |  |  |  | Ebene +2 | 1 | Ne | (10958.244-36)/1000- | 2.07.01_A2_34 | 4 | 7.5 | 1216Rau0000047607
WUN-H2-E02-091 | H2 Ebene +2 | Doppelzimmer |  |  |  | Ebene +2 | 1 | Be | (11493.779-36)/1000- | 2.07.01_A2_16 | 26 | 7.5 | 1216Rau0000047039
WUN-H2-E02-095a | H2 Ebene +2 | Nasszelle DZ |  |  |  | Ebene +2 | 1 | WC | (13092.982-36)/1000- | 2.07.01_A2_23 | 4 | 7.5 | 1216Rau0000046923
WUN-H2-E02-094a | H2 Ebene +2 | Nasszelle DZ |  |  |  | Ebene +2 | 1 | WC | (12900.464-36)/1000- | 2.07.01_A2_22 | 4 | 7.5 | 1216Rau0000046935
WUN-H2-E02-093a | H2 Ebene +2 | Nasszelle EZ | R | N | NUF | Ebene +2 | 1 | WC | (12287.904-36)/1000- | 2.07.01_A2_09 | 4 | 7.5 | 1216Rau0000047001
WUN-H2-E02-092a | H2 Ebene +2 | Nasszelle rsg. | R | N | NUF | Ebene +2 | 1 | WC | (12057.1-36)/1000- | 2.07.01_A2_14 | 6 | 7.5 | 1216Rau0000047013
WUN-H2-E02-096a | H2 Ebene +2 | Nasszelle EZ |  |  |  | Ebene +2 | 1 | WC | (11969.047-36)/1000- | 2.07.01_A2_10 | 4 | 7.5 | 1216Rau0000046897
WUN-H2-E02-095 | H2 Ebene +2 | Doppelzimmer | R | N | NUF | Ebene +2 | 1 | Be | (13243.602-36)/1000- | 2.07.01_A2_18 | 26 | 7.5 | 1216Rau0000046909 | AllplanAttributes - Text1: Achtung Wand in LP 5 in Achse um 2,5cm nach links verschieben!!!; Text4: x
WUN-H2-E02-094 | H2 Ebene +2 | Doppelzimmer | R | N | NUF | Ebene +2 | 1 | Be | (12753.872-36)/1000- | 2.07.01_A2_17 | 26 | 7.5 | 1216Rau0000046947 | AllplanAttributes - Text1: Achtung Wand in LP 5 in Achse um 2,5cm nach links verschieben!!!; Text4: x
WUN-H2-E02-093 | H2 Ebene +2 | Einzelzimmer | R | N | NUF | Ebene +2 | 1 | Be | (12400.032-36)/1000- | 2.07.01_A2_06 | 20 | 7.5 | 1216Rau0000046987
WUN-H2-E02-092 | H2 Ebene +2 | Rollstuhlgerechtes Doppelzimmer | R | N | NUF | Ebene +2 | 1 | Be | (11905.162-36)/1000- | 2.07.01_A2_12 | 26 | 7.5 | 1216Rau0000047025 | AllplanAttributes - Text1: Achtung Wand in LP 5 in Achse um 2,5cm nach rechts verschieben!!!; Text4: x
WUN-H2-E02-096 | H2 Ebene +2 | Einzelzimmer mit Zustelloption | R | B | NUF | Ebene +2 | 1 | Be | (12354.925-36)/1000- | 2.07.01_A2_07 | 25 | 7.5 | 1216Rau0000046883
WUN-H2-E02-091a | H2 Ebene +2 | Nasszelle DZ |  |  |  | Ebene +2 | 1 | WC | (11347.188-36)/1000- | 2.07.01_A2_21 | 4 | 7.5 | 1216Rau0000047053
WUN-H2-E02-090a | H2 Ebene +2 | Nasszelle DZ |  |  |  | Ebene +2 | 1 | WC | (11154.669-36)/1000- | 2.07.01_A2_24 | 4 | 7.5 | 1216Rau0000047065
WUN-H2-E02-090 | H2 Ebene +2 | Doppelzimmer | R | N | NUF | Ebene +2 | 1 | Be | (11006.559-36)/1000- | 2.07.01_A2_19 | 26 | 7.5 | 1216Rau0000047077 | AllplanAttributes - Text1: Achtung Wand in LP 5 in Achse um 2,5cm nach rechts verschieben!!!; Text4: x
WUN-H2-E02-056 | H2 Ebene +2 | Stationsleitung | R | N | NUF | Ebene +2 | 1 | So | 10.900000 | 2.07.01_A2_55 | 16 | 7.5 | 1216Rau0000047131 | AllplanAttributes - Text5: ja
WUN-H2-E02-059 | H2 Ebene +2 | Freizeit / Club | R | N | NUF | Ebene +2 | 1 | So | 10.900000 | 2.07.01_A2_31 | 36 | 7.5 | 1216Rau0000046973
WUN-H2-E02-013a | H2 Ebene +2 | Backoffice | R | N | NUF | Ebene +2 | 1 | Bü | 10.900000 | 2.07.01_A2_49 | 24 | 7.5 | 1216Rau0812652329 | AllplanAttributes - ash R_Verweis Wandansicht: 2006; Text5: ja
WUN-H2-E02-051 | H2 Ebene +2 | Hauswirtschaftsraum | R | N | NUF | Ebene +2 | 1 | So | 10.900000 | 01.12.02_A2_03 | 14 | 7.5 | 1216Rau0000047157 | AllplanAttributes - ash R_Verweis Wandansicht: 2009
WUN-H2-E02-058 | H2 Ebene +2 | Ergo- / Kunsttherapie | R | N | NUF | Ebene +2 | 1 | So | 10.900000 | 01.12.02_A2_01 | 38 | 7.5 | 1216Rau0000047091
WUN-H2-E02-011 | H2 Ebene +2 | AR rein | R | N | NUF | Ebene +2 | 1 | So | 10.900000 | 2.07.01_G1_35 | 16 | 7.5 | 1216Rau0000046587 | AllplanAttributes - ash R_Verweis Wandansicht: 2018; Text5: ja
WUN-H2-E02-065 | H2 Ebene +2 | AR rein | R | N | NUF | Ebene +2 | 1 | So | 10.900000 | 2.07.01_G1_35 | 16 | 7.5 | 1216Rau0000047195 | AllplanAttributes - Text5: ja
WUN-H2-E02-066 | H2 Ebene +2 | Ruheraum | R | N | NUF | Ebene +2 | 1 | So | 10.900000 | 2.07.01_A2_29 | 16 | 7.5 | 1216Rau0000047181 | AllplanAttributes - Text3: Ruheraum
WUN-H2-E02-064a | H2 Ebene +2 | Krisenzimmer 1-Bett | R | N | NUF | Ebene +2 | 1 | Be | 10.900000 | 2.07.01_A2_25 | 16 | 7.5 | 1216Rau0812652342
WUN-H2-E02-012a | H2 Ebene +2 | Krisenzimmer 1-Bett | R | N | NUF | Ebene +2 | 1 | Be | 10.900000 | 2.07.01_G1_25 | 16 | 7.5 | 1216Rau0000046651 | AllplanAttributes - ash R_Verweis Wandansicht: 2007
WUN-H2-E02-005 | H2 Ebene +2 | Ergo- / Kunsttherapie | R | N | NUF | Ebene +2 | 1 | So | 10.900000 | 01.12.02_G1_01 | 38 | 7.5 | 1216Rau0000046419 | AllplanAttributes - ash R_Verweis Wandansicht: 2014
WUN-H2-E02-004 | H2 Ebene +2 | Freizeit / Club | R | N | NUF | Ebene +2 | 1 | So | 10.900000 | 2.07.01_G1_31 | 36 | 7.5 | 1216Rau0000046405 | AllplanAttributes - ash R_Verweis Wandansicht: 2015
WUN-H2-E02-007 | H2 Ebene +2 | Gespräch | R | N | NUF | Ebene +2 | 1 | So | 10.900000 | 2.07.01_G1_55 | 16 | 7.5 | 1216Rau0000046447 | AllplanAttributes - ash R_Verweis Wandansicht: 2030; Text5: ja
WUN-H2-E02-001 | H2 Ebene +2 | Schmutzwäsche, Müll | R | B | NUF | Ebene +2 | 1 | Ne | 10.000000 | 2.07.01_G1_43 | 20 | 7.5 | 1216Rau0000046729
WUN-H2-E02-052 | H2 Ebene +2 | Vorraum WC | R | N | NUF | Ebene +2 | 1 | WC | 10.000000 | 2.07.01_G1_38 | 0 | 7.5 | 1216Rau0000046537 | AllplanAttributes - ash R_Verweis Wandansicht: 2017
WUN-H2-E02-052a | H2 Ebene +2 | WC Pat. | R | N | NUF | Ebene +2 | 1 | WC | 10.000000 | 2.07.01_G1_39 | 3.5 | 7.5 | 1216Rau0000046561 | AllplanAttributes - ash R_Verweis Wandansicht: 2017; Text3: Sanitärraum Pat
WUN-H2-E02-010 | H2 Ebene +2 | Ruheraum | R | N | NUF | Ebene +2 | 1 | So | 10.900000 | 2.07.01_G1_29 | 16 | 7.5 | 1216Rau0000046573 | AllplanAttributes - ash R_Verweis Wandansicht: 2029; Text3: Ruheraum
WUN-H2-E02-012 | H2 Ebene +2 | Vorraum Krisenzimmer | R | N | NUF | Ebene +2 | 1 | Ne | 10.000000 |  | 0 | 7.5 | 1216Rau0000046616
WUN-H2-E02-064 | H2 Ebene +2 | Vorraum Krisenzimmer | R | N | NUF | Ebene +2 | 1 | Ne | 10.000000 |  | 0 | 7.5 | 1216Rau0000046836
WUN-H2-E02-064b | H2 Ebene +2 | WC Krisenzimmer | R | N | NUF | Ebene +2 | 1 | WC | 10.000000 | 2.07.01_A2_27 | 4 | 7.5 | 1216Rau0000046809 | AllplanAttributes - Text3: Patienten
WUN-H2-E02-012b | H2 Ebene +2 | WC Krisenzimmer | R | N | NUF | Ebene +2 | 1 | WC | 10.000000 | 2.07.01_G1_27 | 4 | 7.5 | 1216Rau0000046677 | AllplanAttributes - ash R_Verweis Wandansicht: 2007; Text3: Patienten
WUN-H2-E02-049 | H2 Ebene +2 | Speisewagen |  |  |  | Ebene +2 | 1 | Ne | 10.000000 | 2.07.01_G1_37 | 4 | 7.5 | 1216Rau0000046513
WUN-H2-E02-052b | H2 Ebene +2 | WC Pat. | R | N | NUF | Ebene +2 | 1 | WC | 10.000000 | 2.07.01_G1_38 | 3.5 | 7.5 | 1216Rau0000046549 | AllplanAttributes - ash R_Verweis Wandansicht: 2017; Text3: Sanitärraum Pat
WUN-H2-E02-062 | H2 Ebene +2 | WC Bes. rsg. | R | B | NUF | Ebene +2 | 1 | WC | 10.000000 | 2.07.01_A2_48 | 6 | 7.5 | 1216Rau0000046755 | AllplanAttributes - Text3: Besucher
WUN-H2-E02-F09a | H2 Ebene +2 | Marktplatz | R | N | NUF | Ebene +2 | 1 | Ne | 10.000000 | 2.07.01_A2_32 | 16 | 7.5 | 1216Rau0000047119
WUN-H2-E02-F09b | H2 Ebene +2 | Marktplatz | R | N | NUF | Ebene +2 | 1 | Ne | 10.000000 | 2.07.01_A2_32 | 16 | 7.5 | 1216Rau0000046860
WUN-H2-E02-F03b | H2 Ebene +2 | Marktplatz | R | B | NUF | Ebene +2 | 1 | Ne | 10.000000 | 2.07.01_G1_31 | 0 | 7.5 | 1216Rau0000046637
WUN-H2-E02-F03a | H2 Ebene +2 | Marktplatz | R | B | NUF | Ebene +2 | 1 | Ne | 10.000000 | 2.07.01_G1_31 | 0 | 7.5 | 1216Rau0000046473 | AllplanAttributes - ash R_Verweis Wandansicht: 2030
WUN-H2-E02-063 | H2 Ebene +2 | Dienstraum Pflege | R | N | NUF | Ebene +2 | 1 | Bü | 10.000000 | 2.07.01_A2_32 | 16 | 7.5 | 1216Rau0000046869 | AllplanAttributes - Text5: mittelbar
WUN-H2-E02-013 | H2 Ebene +2 | Dienstraum Pflege | R | N | NUF | Ebene +2 | 1 | Bü | 10.860000 | 2.07.01_A2_49 | 24 | 7.5 | 1216Rau0000046628 | AllplanAttributes - ash R_Verweis Wandansicht: 2006; Text5: mittelbar
WUN-H2-E02-009 | H2 Ebene +2 | U/B-Raum | R | N | NUF | Ebene +2 | 1 | Un | 10.000000 | 1.12.02_G1_03 | 14 | 7.5 | 1216Rau0000046525 | AllplanAttributes - ash R_Verweis Wandansicht: 2016; Text5: nein
WUN-H2-E02-067 | H2 Ebene +2 | U/B-Raum |  |  |  | Ebene +2 | 1 | Un | 10.000000 | 1.12.02_G1_03 | 14 | 7.5 | 1216Rau0000047169 | AllplanAttributes - Text5: nein
WUN-H2-E02-025 | H2 Ebene +2 | Doppelzimmer |  |  |  | Ebene +2 | 1 | Be | (11009.112-36)/1000- | 2.07.01_G1_18 | 26 | 7.5 | 1216Rau0000046211
WUN-H2-E02-S11 | H2 Ebene +2 | Schacht | R | TF | NUF | Ebene +2 | 1 | -- | 10.846989 | RLT | 0 | 7.5 | 1216Rau0000045841
WUN-H2-E02-S10 | H2 Ebene +2 | Schacht | R | TF | NUF | Ebene +2 | 1 | -- | 10.846989 | RLT | 0 | 7.5 | 1216Rau0000045831
WUN-H2-E02-S02 | H2 Ebene +2 | Schacht HLS | R | N | TF | Ebene +2 | 1 | -- | 10.900000 | Technik | 0 | 7.5 | 1216Rau0000046665 | AllplanAttributes - Text1: Schachbreite in LP 5 kleiner; Text4: x
WUN-H2-E02-S06 | H2 Ebene +2 | Schacht HLS | R | N | TF | Ebene +2 | 1 |  | 10.900000 | Technik | 0 | 7.5 | 1216Rau0000047145
WUN-H2-E02-S05 | H2 Ebene +2 | Schacht HLS | R | N | TF | Ebene +2 | 1 | -- | 10.900000 | Technik | 0 | 7.5 | 1216Rau0000046461 | AllplanAttributes - Status: Neubau
WUN-H2-E02-S07 | H2 Ebene +2 | Schacht HLS | R | N | TF | Ebene +2 | 1 | 0 | 10.900000 | Technik | 0 | 7.5 | 1216Rau0000046961
WUN-H2-E02-S04 | H2 Ebene +2 | Schacht HLS | R | N | TF | Ebene +2 | 1 | -- | 10.900000 | Technik | 0 | 7.5 | 1216Rau0000046393
WUN-H2-E02-S03 | H2 Ebene +2 | Schacht warm | R | N | TF | Ebene +2 | 1 | -- | 10.900000 | Technik | 0 | 7.5 | 1216Rau0000046604
WUN-H2-E02-S08 | H2 Ebene +2 | Schacht kalt | R | N | TF | Ebene +2 | 1 | -- | 10.900000 | Technik | 0 | 7.5 | 1216Rau0000046848
WUN-H2-E02-S09 | H2 Ebene +2 | Schacht HLS | R | N | TF | Ebene +2 | 1 | -- | 10.900000 | Technik | 0 | 7.5 | 1216Rau0000046821 | AllplanAttributes - Text1: Schachbreite in LP 5 kleiner; Text4: x
WUN-H2-E02-S01 | H2 Ebene +2 | Hausanschluss | R | N | TF | Ebene +2 | 1 | Ne | 10.864000 | Technik | 0 | 7.5 | 1216Rau0000046743
WUN-H2-E02-053 | H2 Ebene +2 | SV | R | TF | NUF | Ebene +2 | 1 | Ne | 10.864000 | ELT | 10 | 7.5 | 1216Rau0000047237
WUN-H2-E02-054 | H2 Ebene +2 | AV | R | TF | NUF | Ebene +2 | 1 | Ne | 10.864000 | ELT | 10 | 7.5 | 1216Rau0000047249
WUN-H2-E02-088 | H2 Ebene +2 | SV | R | TF | NUF | Ebene +2 | 1 | Ne | 11.166799 | ELT | 10 | 7.5 | 1216Rau0000047595
WUN-H2-E02-028 | H2 Ebene +2 | AV | R | TF | NUF | Ebene +2 | 1 | Ne | 11.363686 | ELT | 10 | 7.5 | 1216Rau0000046199
WUN-H2-E02-027 | H2 Ebene +2 | SV | R | TF | NUF | Ebene +2 | 1 | Ne | 11.166799 | ELT | 10 | 7.5 | 1216Rau0000046187
WUN-H2-E02-087 | H2 Ebene +2 | AV | R | TF | NUF | Ebene +2 | 1 | Ne | 11.363693 | ELT | 10 | 7.5 | 1216Rau0000047583
WUN-H2-E02-002 | H2 Ebene +2 | Lager Versorgungsgüter | R | N | NUF | Ebene +2 | 1 | Ne | (10900-36+764+100)/1000- | 2.07.01_A2_44 | 20 | 7.5 | 1216Rau0000046717
WUN-H2-E01-T04 | H2 Ebene +1 | TH 4 | R | N | VF | Ebene +1 | 1 | Ne | 7.150000 | VF | 0 | 3.75 | 1165Rau0000004782 | AllplanAttributes - Status: Neubau; BauNVO_Anrechnung_auf_GR: 0; BauNVO_Anrechnung_auf_GF: 0; ash D_Detailverweis: TRH4; ash D_Plannummer: D1528; Pset_SpaceCommon - IsExternal: no; HandicapAccessible: no; Pset_SpaceFireSafetyRequirements - FireExit: no; FireRiskFaktor: A; SprinklerProtection: no; Pset_SpaceLightingRequirements - ArtificialLighting: no; Pset_SpaceThermalRequirements - SpaceHumidity: 0; NaturalVentilation: no; AirConditioning: no; SpaceTemperatureMin: 0; SpaceTemperatureMax: 0
WUN-H2-E01-A01 | H2 Ebene +1 | A2 | R | N | VF | Ebene +1 | 1 | -- | 7.150000 | VF | 0 | 3.75 | 1165Rau0000004793 | AllplanAttributes - Status: Neubau; BauNVO_Anrechnung_auf_GR: 0; BauNVO_Anrechnung_auf_GF: 0; ash D_Detailverweis: D1502; ash D_Plannummer: D1501; Pset_SpaceCommon - IsExternal: no; HandicapAccessible: no; Pset_SpaceFireSafetyRequirements - FireExit: no; FireRiskFaktor: A; SprinklerProtection: no; Pset_SpaceLightingRequirements - ArtificialLighting: no; Pset_SpaceThermalRequirements - SpaceHumidity: 0; NaturalVentilation: no; AirConditioning: no; SpaceTemperatureMin: 0; SpaceTemperatureMax: 0
WUN-H2-E01-A02 | H2 Ebene +1 | A1 | R | N | VF | Ebene +1 | 1 | -- | 7.150000 | VF | 0 | 3.75 | 1165Rau0000004804 | AllplanAttributes - Status: Neubau; BauNVO_Anrechnung_auf_GR: 0; BauNVO_Anrechnung_auf_GF: 0; ash D_Detailverweis: D1502; ash D_Plannummer: D1501; Pset_SpaceCommon - IsExternal: no; HandicapAccessible: no; Pset_SpaceFireSafetyRequirements - FireExit: no; FireRiskFaktor: A; SprinklerProtection: no; Pset_SpaceLightingRequirements - ArtificialLighting: no; Pset_SpaceThermalRequirements - SpaceHumidity: 0; NaturalVentilation: no; AirConditioning: no; SpaceTemperatureMin: 0; SpaceTemperatureMax: 0
WUN-H2-E01-T01 | H2 Ebene +1 | TH 1 | R | N | VF | Ebene +1 | 1 | Ne | 7.150000 | VF | 0 | 3.75 | 1165Rau0000004749 | AllplanAttributes - BauNVO_Anrechnung_auf_GR: 0; BauNVO_Anrechnung_auf_GF: 0; ash D_Detailverweis: TRH1; ash D_Plannummer: D1525; ash R_Verweis Wandansicht: 1537; Pset_SpaceCommon - IsExternal: no; HandicapAccessible: no; Pset_SpaceFireSafetyRequirements - FireExit: no; FireRiskFaktor: A; SprinklerProtection: no; Pset_SpaceLightingRequirements - ArtificialLighting: no; Pset_SpaceThermalRequirements - SpaceHumidity: 0; NaturalVentilation: no; AirConditioning: no; SpaceTemperatureMin: 0; SpaceTemperatureMax: 0
WUN-H2-E01-T02 | H2 Ebene +1 | TH 2 | R | N | VF | Ebene +1 | 1 | Ne | 7.150000 | VF | 0 | 3.75 | 1165Rau0000004760 | AllplanAttributes - Status: Neubau; BauNVO_Anrechnung_auf_GR: 0; BauNVO_Anrechnung_auf_GF: 0; ash D_Detailverweis: TRH2; ash D_Plannummer: D1526; ash R_Verweis Wandansicht: 1538; Pset_SpaceCommon - IsExternal: no; HandicapAccessible: no; Pset_SpaceFireSafetyRequirements - FireExit: no; FireRiskFaktor: A; SprinklerProtection: no; Pset_SpaceLightingRequirements - ArtificialLighting: no; Pset_SpaceThermalRequirements - SpaceHumidity: 0; NaturalVentilation: no; AirConditioning: no; SpaceTemperatureMin: 0; SpaceTemperatureMax: 0
WUN-H2-E01-F02 | H2 Ebene +1 | Flur | R | N | VF | Ebene +1 | 1 | Ne | 6.850000 | VF | 0 | 3.75 | 1165Rau0000004666 | AllplanAttributes - BauNVO_Anrechnung_auf_GR: 0; BauNVO_Anrechnung_auf_GF: 0; Pset_SpaceCommon - IsExternal: no; HandicapAccessible: no; Pset_SpaceFireSafetyRequirements - FireExit: no; FireRiskFaktor: A; SprinklerProtection: no; Pset_SpaceLightingRequirements - ArtificialLighting: no; Pset_SpaceThermalRequirements - SpaceHumidity: 0; NaturalVentilation: no; AirConditioning: no; SpaceTemperatureMin: 0; SpaceTemperatureMax: 0
WUN-H2-E01-073 | H2 Ebene +1 | Ruheraum |  |  |  | Ebene +1 | 1 | Be | 6.850000 | 2.11_A2_01 | 25 | 3.75 | 1165Rau0000004651 | AllplanAttributes - Status: Neubau; BauNVO_Anrechnung_auf_GR: 0; BauNVO_Anrechnung_auf_GF: 0; Pset_SpaceCommon - IsExternal: no; HandicapAccessible: no; Pset_SpaceFireSafetyRequirements - FireExit: no; FireRiskFaktor: A; SprinklerProtection: no; Pset_SpaceLightingRequirements - ArtificialLighting: no; Pset_SpaceThermalRequirements - SpaceHumidity: 0; NaturalVentilation: no; AirConditioning: no; SpaceTemperatureMin: 0; SpaceTemperatureMax: 0
WUN-H2-E01-073 | H2 Ebene +1 | Ruheraum |  |  |  | Ebene +1 | 1 | Be | 7.150000 | 2.11_A2_01 | 25 | 3.75 | 1165Rau0000004688 | AllplanAttributes - BauNVO_Anrechnung_auf_GR: 0; BauNVO_Anrechnung_auf_GF: 0; ash R_Verweis Wandansicht: 2005; Pset_SpaceCommon - IsExternal: no; HandicapAccessible: no; Pset_SpaceFireSafetyRequirements - FireExit: no; FireRiskFaktor: A; SprinklerProtection: no; Pset_SpaceLightingRequirements - ArtificialLighting: no; Pset_SpaceThermalRequirements - SpaceHumidity: 0; NaturalVentilation: no; AirConditioning: no; SpaceTemperatureMin: 0; SpaceTemperatureMax: 0
WUN-H2-E01-073 | H2 Ebene +1 | Ruheraum |  |  |  | Ebene +1 | 1 | Be | 6.250000 | 2.11_A2_01 | 25 | 3.75 | 1165Rau0000004677 | AllplanAttributes - Status: Neubau; BauNVO_Anrechnung_auf_GR: 0; BauNVO_Anrechnung_auf_GF: 0; Pset_SpaceCommon - IsExternal: no; HandicapAccessible: no; Pset_SpaceFireSafetyRequirements - FireExit: no; FireRiskFaktor: A; SprinklerProtection: no; Pset_SpaceLightingRequirements - ArtificialLighting: no; Pset_SpaceThermalRequirements - SpaceHumidity: 0; NaturalVentilation: no; AirConditioning: no; SpaceTemperatureMin: 0; SpaceTemperatureMax: 0
WUN-H2-E01-073 | H2 Ebene +1 | Ruheraum |  |  |  | Ebene +1 | 1 | Be | 6.850000 | 2.11_A2_01 | 25 | 3.75 | 1165Rau0000004712 | AllplanAttributes - Status: Neubau; BauNVO_Anrechnung_auf_GR: 0; BauNVO_Anrechnung_auf_GF: 0; Pset_SpaceCommon - IsExternal: no; HandicapAccessible: no; Pset_SpaceFireSafetyRequirements - FireExit: no; FireRiskFaktor: A; SprinklerProtection: no; Pset_SpaceLightingRequirements - ArtificialLighting: no; Pset_SpaceThermalRequirements - SpaceHumidity: 0; NaturalVentilation: no; AirConditioning: no; SpaceTemperatureMin: 0; SpaceTemperatureMax: 0
WUN-H2-E01-073 | H2 Ebene +1 | Ruheraum |  |  |  | Ebene +1 | 1 | Be | 6.850000 | 2.11_A2_01 | 25 | 3.75 | 1165Rau0000004736 | AllplanAttributes - Status: Neubau; BauNVO_Anrechnung_auf_GR: 0; BauNVO_Anrechnung_auf_GF: 0; Pset_SpaceCommon - IsExternal: no; HandicapAccessible: no; Pset_SpaceFireSafetyRequirements - FireExit: no; FireRiskFaktor: A; SprinklerProtection: no; Pset_SpaceLightingRequirements - ArtificialLighting: no; Pset_SpaceThermalRequirements - SpaceHumidity: 0; NaturalVentilation: no; AirConditioning: no; SpaceTemperatureMin: 0; SpaceTemperatureMax: 0
WUN-H2-E01-073 | H2 Ebene +1 | Ruheraum |  |  |  | Ebene +1 | 1 | Be | 6.250000 | 2.11_A2_01 | 25 | 3.75 | 1165Rau0000004725 | AllplanAttributes - Status: Neubau; BauNVO_Anrechnung_auf_GR: 0; BauNVO_Anrechnung_auf_GF: 0; Pset_SpaceCommon - IsExternal: no; HandicapAccessible: no; Pset_SpaceFireSafetyRequirements - FireExit: no; FireRiskFaktor: A; SprinklerProtection: no; Pset_SpaceLightingRequirements - ArtificialLighting: no; Pset_SpaceThermalRequirements - SpaceHumidity: 0; NaturalVentilation: no; AirConditioning: no; SpaceTemperatureMin: 0; SpaceTemperatureMax: 0
WUN-H2-E01-F01 | H2 Ebene +1 | Foyer | R | N | VF | Ebene +1 | 1 | Ne | 6.500000 | VF | 0 | 3.75 | 1165Rau0000067051 | AllplanAttributes - BauNVO_Anrechnung_auf_GR: 0; BauNVO_Anrechnung_auf_GF: 0; Pset_SpaceCommon - IsExternal: no; HandicapAccessible: no; Pset_SpaceFireSafetyRequirements - FireExit: no; FireRiskFaktor: A; SprinklerProtection: no; Pset_SpaceLightingRequirements - ArtificialLighting: no; Pset_SpaceThermalRequirements - SpaceHumidity: 0; NaturalVentilation: no; AirConditioning: no; SpaceTemperatureMin: 0; SpaceTemperatureMax: 0
WUN-H2-E01-F08 | H2 Ebene +1 | Flur | R | N | VF | Ebene +1 | 1 | Ne | 6.250000 | VF | 0 | 3.75 | 1165Rau0000004701 | AllplanAttributes - Status: Neubau; BauNVO_Anrechnung_auf_GR: 0; BauNVO_Anrechnung_auf_GF: 0; Pset_SpaceCommon - IsExternal: no; HandicapAccessible: no; Pset_SpaceFireSafetyRequirements - FireExit: no; FireRiskFaktor: A; SprinklerProtection: no; Pset_SpaceLightingRequirements - ArtificialLighting: no; Pset_SpaceThermalRequirements - SpaceHumidity: 0; NaturalVentilation: no; AirConditioning: no; SpaceTemperatureMin: 0; SpaceTemperatureMax: 0
WUN-H2-E01-F03 | H2 Ebene +1 | Flur | R | N | VF | Ebene +1 | 1 | Ne | 7.150000 | VF | 0 | 3.75 | 1165Rau0000004808 | AllplanAttributes - Status: Neubau; BauNVO_Anrechnung_auf_GR: 0; BauNVO_Anrechnung_auf_GF: 0; Pset_SpaceCommon - IsExternal: no; HandicapAccessible: no; Pset_SpaceFireSafetyRequirements - FireExit: no; FireRiskFaktor: A; SprinklerProtection: no; Pset_SpaceLightingRequirements - ArtificialLighting: no; Pset_SpaceThermalRequirements - SpaceHumidity: 0; NaturalVentilation: no; AirConditioning: no; SpaceTemperatureMin: 0; SpaceTemperatureMax: 0
WUN-H2-E01-T03 | H2 Ebene +1 | TH 3 | R | N | VF | Ebene +1 | 1 | Ne | 7.150000 | VF | 0 | 3.75 | 1165Rau0000004771 | AllplanAttributes - Status: Neubau; BauNVO_Anrechnung_auf_GR: 0; BauNVO_Anrechnung_auf_GF: 0; ash D_Detailverweis: TRH3; ash D_Plannummer: D1527; Pset_SpaceCommon - IsExternal: no; HandicapAccessible: no; Pset_SpaceFireSafetyRequirements - FireExit: no; FireRiskFaktor: A; SprinklerProtection: no; Pset_SpaceLightingRequirements - ArtificialLighting: no; Pset_SpaceThermalRequirements - SpaceHumidity: 0; NaturalVentilation: no; AirConditioning: no; SpaceTemperatureMin: 0; SpaceTemperatureMax: 0
WUN-H2-E01-F07 | H2 Ebene +1 | Flur | R | N | VF | Ebene +1 | 1 | Ne | 7.150000 | VF | 0 | 3.75 | 1165Rau0000004819 | AllplanAttributes - Status: Neubau; BauNVO_Anrechnung_auf_GR: 0; BauNVO_Anrechnung_auf_GF: 0; Pset_SpaceCommon - IsExternal: no; HandicapAccessible: no; Pset_SpaceFireSafetyRequirements - FireExit: no; FireRiskFaktor: A; SprinklerProtection: no; Pset_SpaceLightingRequirements - ArtificialLighting: no; Pset_SpaceThermalRequirements - SpaceHumidity: 0; NaturalVentilation: no; AirConditioning: no; SpaceTemperatureMin: 0; SpaceTemperatureMax: 0
WUN-H2-E01-012b | H2 Ebene +1 | WC Krisenzimmer | R | N | NUF | Ebene +1 | 1 | WC | 6.250000 | 2.07.01_G1_27 | 4 | 3.75 | 1166Rau0000033251 | AllplanAttributes - ash R_Verweis Wandansicht: 2007; Text3: Patienten
WUN-H2-E01-052b | H2 Ebene +1 | WC Pat. | R | N | NUF | Ebene +1 | 1 | WC | 6.250000 | 2.07.01_G1_38 | 3.5 | 3.75 | 1166Rau0000033847 | AllplanAttributes - ash R_Verweis Wandansicht: 2017; Text3: Patienten
WUN-H2-E01-S05 | H2 Ebene +1 | Schacht HLS | R | N | TF | Ebene +1 | 1 | -- | 7.150000 | Technik | 0 | 3.75 | 1166Rau0000034646
WUN-H2-E01-S02 | H2 Ebene +1 | Schacht HLS | R | N | TF | Ebene +1 | 1 | -- | 7.150000 | Technik | 0 | 3.75 | 1166Rau0000034613 | AllplanAttributes - Text1: Schachbreite in LP 5 kleiner; Text4: x
WUN-H2-E01-S03 | H2 Ebene +1 | Schacht warm | R | N | TF | Ebene +1 | 1 | -- | 7.150000 | Technik | 0 | 3.75 | 1166Rau0000034624
WUN-H2-E01-S08 | H2 Ebene +1 | Schacht kalt | R | N | TF | Ebene +1 | 1 | -- | 7.150000 | Technik | 0 | 3.75 | 1166Rau0000034657
WUN-H2-E01-S04 | H2 Ebene +1 | Schacht HLS | R | N | TF | Ebene +1 | 1 | -- | 7.150000 | Technik | 0 | 3.75 | 1166Rau0000034635
WUN-H2-E01-S06 | H2 Ebene +1 | Schacht HLS | R | N | TF | Ebene +1 | 1 | -- | 7.150000 | Technik | 0 | 3.75 | 1166Rau0000034679
WUN-H2-E01-S07 | H2 Ebene +1 | Schacht HLS | R | N | TF | Ebene +1 | 1 | -- | 7.150000 | Technik | 0 | 3.75 | 1166Rau0000034668
WUN-H2-E01-S09 | H2 Ebene +1 | Schacht HLS | R | N | TF | Ebene +1 | 1 | -- | 7.150000 | Technik | 0 | 3.75 | 1166Rau0000034602 | AllplanAttributes - Text1: Schachbreite in LP 5 kleiner; Text4: x
WUN-H2-E01-S10 | H2 Ebene +1 | Schacht | R | N | TF | Ebene +1 | 1 | -- | 7.150000 | Technik | 0 | 3.75 | 1166Rau0000135207
WUN-H2-E01-S11 | H2 Ebene +1 | Schacht | R | N | TF | Ebene +1 | 1 | -- | 7.150000 | Technik | 0 | 3.75 | 1166Rau0000135346
WUN-H2-E01-052a | H2 Ebene +1 | WC Pat. | R | N | NUF | Ebene +1 | 1 | WC | 6.250000 | 2.07.01_G1_39 | 3.5 | 3.75 | 1166Rau0000033840 | AllplanAttributes - ash R_Verweis Wandansicht: 2017; Text3: Patienten
WUN-H2-E01-L01 | H2 Ebene +1 | Loggia I | S | N | NUF | Ebene +1 | 1 | So | (7070-180+45)/1000- |  | 0 | 3.75 | 1166Rau0000438355 | AllplanAttributes - ash D_Detailverweis: Außen; ash D_Plannummer: D1556
WUN-H2-E01-L02 | H2 Ebene +1 | Loggia II | S | N | NUF | Ebene +1 | 1 | So | (7070-180+45)/1000- |  | 0 | 3.75 | 1166Rau0000438330 | AllplanAttributes - ash D_Detailverweis: Außen; ash D_Plannummer: D1555
WUN-H2-E01-079 | H2 Ebene +1 | WC Pers. | R | N | NUF | Ebene +1 | 1 | WC | (7150-36+764+100)/1000- | 2.07.01_A2_56 | 3.5 | 3.75 | 1166Rau0000034283 | AllplanAttributes - Text3: Sanitärraum
WUN-H2-E01-080 | H2 Ebene +1 | WC Pers. | R | N | NUF | Ebene +1 | 1 | WC | (7150-36+764+100)/1000- | 2.07.01_A2_57 | 3.5 | 3.75 | 1166Rau0000034294 | AllplanAttributes - Text3: Sanitärraum
WUN-H2-E01-041 | H2 Ebene +1 | Ruheraum | R | N | NUF | Ebene +1 | 1 | Be | 6.900000 | 2.11_G1_01 | 25 | 3.75 | 1166Rau0000033547
WUN-H2-E01-041a | H2 Ebene +1 | Bad mit Dusche |  |  |  | Ebene +1 | 1 | WC | 6.250000 | 2.11_G1_03 | 4 | 3.75 | 1166Rau0000033715
WUN-H2-E01-090 | H2 Ebene +1 | Doppelzimmer | R | N | NUF | Ebene +1 | 1 | Be | 6.900000 | 2.07.01_A2_19 | 26 | 3.75 | 1166Rau0000034401 | AllplanAttributes - Text1: Achtung Wand in LP 5 in Achse um 2,5cm nach rechts verschieben!!!; Text4: x
WUN-H2-E01-091 | H2 Ebene +1 | Doppelzimmer |  |  |  | Ebene +1 | 1 | Be | 6.900000 | 2.07.01_A2_16 | 26 | 3.75 | 1166Rau0000034414
WUN-H2-E01-092 | H2 Ebene +1 | Rollstuhlgerechtes Doppelzimmer | R | N | NUF | Ebene +1 | 1 | Be | 6.900000 | 2.07.01_A2_12 | 26 | 3.75 | 1166Rau0000034427 | AllplanAttributes - Text1: Achtung Wand in LP 5 in Achse um 2,5cm nach rechts verschieben!!!; Text4: x
WUN-H2-E01-093 | H2 Ebene +1 | Einzelzimmer | R | N | NUF | Ebene +1 | 1 | Be | 6.900000 | 2.07.01_A2_06 | 20 | 3.75 | 1166Rau0000034440
WUN-H2-E01-094 | H2 Ebene +1 | Doppelzimmer | R | N | NUF | Ebene +1 | 1 | Be | 6.900000 | 2.07.01_A2_17 | 26 | 3.75 | 1166Rau0000034497 | AllplanAttributes - Text1: Achtung Wand in LP 5 in Achse um 2,5cm nach links verschieben!!!; Text4: x
WUN-H2-E01-095 | H2 Ebene +1 | Doppelzimmer | R | N | NUF | Ebene +1 | 1 | Be | 6.900000 | 2.07.01_A2_18 | 26 | 3.75 | 1166Rau0000034521 | AllplanAttributes - Text1: Achtung Wand in LP 5 in Achse um 2,5cm nach links verschieben!!!; Text4: x
WUN-H2-E01-096 | H2 Ebene +1 | Einzelzimmer mit Zustelloption | R | B | NUF | Ebene +1 | 1 | Be | 6.900000 | 2.07.01_A2_07 | 25 | 3.75 | 1166Rau0000034545
WUN-H2-E01-019 | H2 Ebene +1 | Einzelzimmer mit Zustelloption | R | N | NUF | Ebene +1 | 1 | Be | 6.900000 | 2.07.01_G1_05 | 25 | 3.75 | 1166Rau0000033294
WUN-H2-E01-020 | H2 Ebene +1 | Doppelzimmer | R | B | NUF | Ebene +1 | 1 | Be | 6.900000 | 2.07.01_G1_15 | 26 | 3.75 | 1166Rau0000033307
WUN-H2-E01-047 | H2 Ebene +1 | Einzelzimmer Adipositas | R | N | NUF | Ebene +1 | 1 | Be | 6.900000 | 2.07.01_G1_05 | 20 | 3.75 | 1166Rau0000033625 | AllplanAttributes - Status: Neubau; ash R_Verweis Wandansicht: 2004
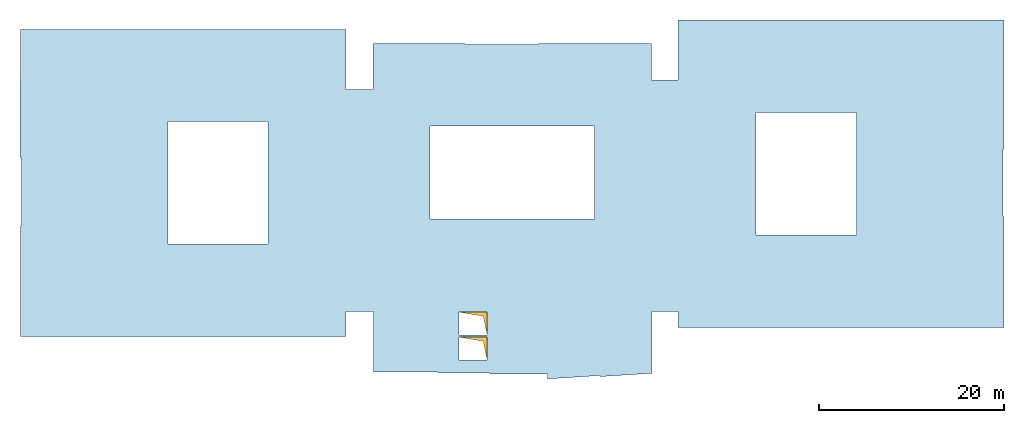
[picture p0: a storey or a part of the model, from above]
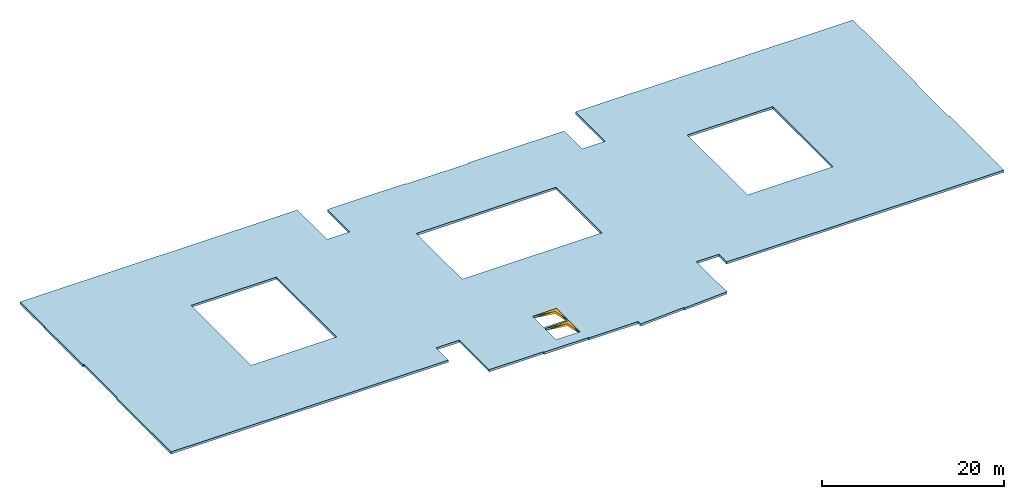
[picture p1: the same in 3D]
Properties of the parts of a building model (IFC4), part 2 of 80

# IfcSpace (512)
Name | In | LongName | Raumumschließung | Flächenart_DIN277 | Nutzungsart_Din277 | Ortscode_Geschoßbezeichnung | Faktor_Wohnfläche_Raum | Raumzone (nach DIN 18599) | ash_lichte Raumhöhe | Raumnr. Bauherr | Raumprogramm Soll (m2) | OKFF | Allright_Bauteil_ID
WUN-H2-E01-046 | H2 Ebene +1 | Einzelzimmer mit Zustelloption |  |  |  | Ebene +1 | 1 | Be | 6.900000 | 2.07.01_G1_01 | 25 | 3.75 | 1166Rau0000033612 | AllplanAttributes - Status: Neubau
WUN-H2-E01-045 | H2 Ebene +1 | Doppelzimmer | R | N | NUF | Ebene +1 | 1 | Be | 6.900000 | 2.07.01_G1_19 | 26 | 3.75 | 1166Rau0000033599 | AllplanAttributes - Status: Neubau; ash R_Verweis Wandansicht: 2001
WUN-H2-E01-044 | H2 Ebene +1 | Einzelzimmer | R | N | NUF | Ebene +1 | 1 | Be | 6.900000 | 2.07.01_G1_07 | 20 | 3.75 | 1166Rau0000033586 | AllplanAttributes - Status: Neubau; ash R_Verweis Wandansicht: 2002
WUN-H2-E01-042 | H2 Ebene +1 | Ruheraum | R | N | NUF | Ebene +1 | 1 | Be | 6.900000 | 2.11_G1_02 | 25 | 3.75 | 1166Rau0000033560 | AllplanAttributes - Status: Neubau; ash R_Verweis Wandansicht: 2003
WUN-H2-E01-043 | H2 Ebene +1 | Rollstuhlgerechtes Doppelzimmer | R | N | NUF | Ebene +1 | 1 | Be | 6.900000 | 2.07.01_G1_12 | 26 | 3.75 | 1166Rau0000033573 | AllplanAttributes - Status: Neubau; ash R_Verweis Wandansicht: 2024
WUN-H2-E01-069 | H2 Ebene +1 | Einzelzimmer mit Zustelloption | R | N | NUF | Ebene +1 | 1 | Be | 6.900000 | 2.07.01_A2_01 | 25 | 3.75 | 1166Rau0000033875 | AllplanAttributes - Text1: Achtung Wand in LP 5 in Achse um 2,5cm nach links verschieben!!!; Text4: x
WUN-H2-E01-074 | H2 Ebene +1 | Ruheraum | R | N | NUF | Ebene +1 | 1 | Be | 6.900000 | 2.11_A2_02 | 25 | 3.75 | 1166Rau0000033940 | AllplanAttributes - Text1: Achtung Wand in LP 5 in Achse um 2,5cm nach rechts verschieben!!!; Text4: x
WUN-H2-E01-073 | H2 Ebene +1 | Ruheraum |  |  |  | Ebene +1 | 1 | Be | 6.900000 | 2.11_A2_01 | 25 | 3.75 | 1166Rau0000033927
WUN-H2-E01-070 | H2 Ebene +1 | Doppelzimmer | R | N | NUF | Ebene +1 | 1 | Be | 6.900000 | 2.07.01_A2_15 | 26 | 3.75 | 1166Rau0000033888 | AllplanAttributes - Text1: Achtung Wand in LP 5 in Achse um 2,5cm nach links verschieben!!!; Text4: x
WUN-H2-E01-072 | H2 Ebene +1 | Rollstuhlgerechtes Doppelzimmer | R | N | NUF | Ebene +1 | 1 | Be | 6.900000 | 2.07.01_A2_11 | 26 | 3.75 | 1166Rau0000033914
WUN-H2-E01-071 | H2 Ebene +1 | Einzelzimmer |  |  |  | Ebene +1 | 1 | Be | 6.900000 | 2.07.01_A2_05 | 20 | 3.75 | 1166Rau0000033901
WUN-H2-E01-068 | H2 Ebene +1 | Einzelzimmer Adipositas | R | N | NUF | Ebene +1 | 1 | Be | 6.900000 | 2.07.01_A2_07 | 20 | 3.75 | 1166Rau0000033862
WUN-H2-E01-021 | H2 Ebene +1 | Doppelzimmer |  |  |  | Ebene +1 | 1 | Be | 6.900000 | 2.07.01_G1_16 | 26 | 3.75 | 1166Rau0000033320
WUN-H2-E01-022 | H2 Ebene +1 | Einzelzimmer | R | N | NUF | Ebene +1 | 1 | Be | 6.900000 | 2.07.01_G1_06 | 20 | 3.75 | 1166Rau0000033333
WUN-H2-E01-023 | H2 Ebene +1 | Rollstuhlgerechtes Doppelzimmer | R | N | NUF | Ebene +1 | 1 | Be | 6.900000 | 2.07.01_G1_11 | 26 | 3.75 | 1166Rau0000033346
WUN-H2-E01-024 | H2 Ebene +1 | Doppelzimmer | R | N | NUF | Ebene +1 | 1 | Be | 6.900000 | 2.07.01_G1_17 | 26 | 3.75 | 1166Rau0000033359
WUN-H2-E01-025 | H2 Ebene +1 | Doppelzimmer |  |  |  | Ebene +1 | 1 | Be | 6.900000 | 2.07.01_G1_18 | 26 | 3.75 | 1166Rau0000033372
WUN-H2-E01-090a | H2 Ebene +1 | Nasszelle DZ |  |  |  | Ebene +1 | 1 | WC | 6.250000 | 2.07.01_A2_24 | 4 | 3.75 | 1166Rau0000034453
WUN-H2-E01-069a | H2 Ebene +1 | Nasszelle EZ+ |  |  |  | Ebene +1 | 1 | WC | 6.250000 | 2.07.01_A2_03 | 4 | 3.75 | 1166Rau0000033964
WUN-H2-E01-070a | H2 Ebene +1 | Nasszelle DZ |  |  |  | Ebene +1 | 1 | WC | 6.250000 | 2.07.01_A2_20 | 4 | 3.75 | 1166Rau0000033975
WUN-H2-E01-071a | H2 Ebene +1 | Nasszelle EZ |  |  |  | Ebene +1 | 1 | WC | 6.250000 | 2.07.01_A2_08 | 4 | 3.75 | 1166Rau0000033986
WUN-H2-E01-072a | H2 Ebene +1 | Nasszelle rsg. |  |  |  | Ebene +1 | 1 | WC | 6.250000 | 2.07.01_A2_13 | 6 | 3.75 | 1166Rau0000033997
WUN-H2-E01-073a | H2 Ebene +1 | Bad mit Dusche |  |  |  | Ebene +1 | 1 | WC | 6.250000 | 2.11_A2_03 | 4 | 3.75 | 1166Rau0000034008
WUN-H2-E01-074a | H2 Ebene +1 | Bad mit Dusche |  |  |  | Ebene +1 | 1 | WC | 6.250000 | 2.11_A2_04 | 4 | 3.75 | 1166Rau0000034019
WUN-H2-E01-092a | H2 Ebene +1 | Nasszelle rsg. | R | N | NUF | Ebene +1 | 1 | WC | 6.250000 | 2.07.01_A2_14 | 6 | 3.75 | 1166Rau0000034475
WUN-H2-E01-020a | H2 Ebene +1 | Nasszelle DZ |  |  |  | Ebene +1 | 1 | WC | 6.250000 | 2.07.01_G1_21 | 4 | 3.75 | 1166Rau0000033649
WUN-H2-E01-021a | H2 Ebene +1 | Nasszelle DZ |  |  |  | Ebene +1 | 1 | WC | 6.250000 | 2.07.01_G1_22 | 4 | 3.75 | 1166Rau0000033660
WUN-H2-E01-022a | H2 Ebene +1 | Nasszelle EZ | R | N | NUF | Ebene +1 | 1 | WC | 6.250000 | 2.07.01_G1_09 | 4 | 3.75 | 1166Rau0000033671
WUN-H2-E01-023a | H2 Ebene +1 | Nasszelle rsg. | R | N | NUF | Ebene +1 | 1 | WC | 6.250000 | 2.07.01_G1_13 | 6 | 3.75 | 1166Rau0000033682
WUN-H2-E01-024a | H2 Ebene +1 | Nasszelle DZ |  |  |  | Ebene +1 | 1 | WC | 6.250000 | 2.07.01_G1_23 | 4 | 3.75 | 1166Rau0000033693
WUN-H2-E01-025a | H2 Ebene +1 | Nasszelle DZ |  |  |  | Ebene +1 | 1 | WC | 6.250000 | 2.07.01_G1_20 | 4 | 3.75 | 1166Rau0000033704
WUN-H2-E01-095a | H2 Ebene +1 | Nasszelle DZ |  |  |  | Ebene +1 | 1 | WC | 6.250000 | 2.07.01_A2_23 | 4 | 3.75 | 1166Rau0000034534
WUN-H2-E01-094a | H2 Ebene +1 | Nasszelle DZ |  |  |  | Ebene +1 | 1 | WC | 6.250000 | 2.07.01_A2_22 | 4 | 3.75 | 1166Rau0000034510
WUN-H2-E01-093a | H2 Ebene +1 | Nasszelle EZ | R | N | NUF | Ebene +1 | 1 | WC | 6.250000 | 2.07.01_A2_09 | 4 | 3.75 | 1166Rau0000034486
WUN-H2-E01-068a | H2 Ebene +1 | Nasszelle EZ | R | N | NUF | Ebene +1 | 1 | WC | 6.250000 | 2.07.01_A2_10 | 4 | 3.75 | 1166Rau0000033953
WUN-H2-E01-047a | H2 Ebene +1 | Nasszelle EZ | R | N | NUF | Ebene +1 | 1 | WC | 6.250000 | 2.07.01_G1_08 | 4 | 3.75 | 1166Rau0000033781 | AllplanAttributes - ash R_Verweis Wandansicht: 2004
WUN-H2-E01-046a | H2 Ebene +1 | Nasszelle EZ+ |  |  |  | Ebene +1 | 1 | WC | 6.250000 | 2.07.01_G1_03 | 4 | 3.75 | 1166Rau0000033770
WUN-H2-E01-045a | H2 Ebene +1 | Nasszelle DZ | R | N | NUF | Ebene +1 | 1 | WC | 6.250000 | 2.07.01_G1_24 | 4 | 3.75 | 1166Rau0000033759 | AllplanAttributes - ash R_Verweis Wandansicht: 2001
WUN-H2-E01-044a | H2 Ebene +1 | Nasszelle EZ | R | N | NUF | Ebene +1 | 1 | WC | 6.250000 | 2.07.01_G1_10 | 4 | 3.75 | 1166Rau0000033748 | AllplanAttributes - ash R_Verweis Wandansicht: 2002
WUN-H2-E01-043a | H2 Ebene +1 | Nasszelle rsg. | R | N | NUF | Ebene +1 | 1 | WC | 6.250000 | 2.07.01_G1_14 | 6 | 3.75 | 1166Rau0000033737 | AllplanAttributes - ash R_Verweis Wandansicht: 2024
WUN-H2-E01-019a | H2 Ebene +1 | Nasszelle EZ+ |  |  |  | Ebene +1 | 1 | WC | 6.250000 | 2.07.01_G1_04 | 4 | 3.75 | 1166Rau0000033638
WUN-H2-E01-096a | H2 Ebene +1 | Nasszelle EZ |  |  |  | Ebene +1 | 1 | WC | 6.250000 | 2.07.01_A2_10 | 4 | 3.75 | 1166Rau0000034558
WUN-H2-E01-042a | H2 Ebene +1 | Bad mit Dusche | R | N | NUF | Ebene +1 | 1 | WC | 6.250000 | 2.11_G1_04 | 4 | 3.75 | 1166Rau0000033726 | AllplanAttributes - ash R_Verweis Wandansicht: 2003
WUN-H2-E01-091a | H2 Ebene +1 | Nasszelle DZ |  |  |  | Ebene +1 | 1 | WC | 6.250000 | 2.07.01_A2_21 | 4 | 3.75 | 1166Rau0000034464
WUN-H2-E01-036 | H2 Ebene +1 | Sprechzimmer |  |  |  | Ebene +1 | 1 | Bü | 7.150000 | 2.07.01_G1_51 | 16 | 3.75 | 1166Rau0000033499 | AllplanAttributes - Text5: ja
WUN-H2-E01-035 | H2 Ebene +1 | Pause Personal | R | N | NUF | Ebene +1 | 1 | So | 7.150000 | 2.07.01_G1_58 | 14 | 3.75 | 1166Rau0000034731 | AllplanAttributes - ash R_Verweis Wandansicht: 2012; Text1: Standardvorgaben Ausstattung nicht erfüllt; Text4: x; Text5: ja; Text3: Pausenraum
WUN-H2-E01-034 | H2 Ebene +1 | Sprechzimmer |  |  |  | Ebene +1 | 1 | Bü | 7.150000 | 2.07.01_G1_50 | 16 | 3.75 | 1166Rau0000033486 | AllplanAttributes - Text5: ja
WUN-H2-E01-033 | H2 Ebene +1 | Sprechzimmer | R | N | NUF | Ebene +1 | 1 | Bü | 7.150000 | 2.07.01_G1_52 | 16 | 3.75 | 1166Rau0000033473 | AllplanAttributes - ash R_Verweis Wandansicht: 2010; Text5: ja
WUN-H2-E01-037 | H2 Ebene +1 | Sprechzimmer |  |  |  | Ebene +1 | 1 | Bü | 7.150000 | 2.07.01_G1_53 | 16 | 3.75 | 1166Rau0000033512 | AllplanAttributes - Text5: ja
WUN-H2-E01-027 | H2 Ebene +1 | SV | R | TF | NUF | Ebene +1 | 1 | Ne | 7.114000 | ELT | 10 | 3.75 | 1166Rau0000033396
WUN-H2-E01-028 | H2 Ebene +1 | AV | R | TF | NUF | Ebene +1 | 1 | Ne | 7.114000 | ELT | 10 | 3.75 | 1166Rau0000033407
WUN-H2-E01-040 | H2 Ebene +1 | Geräte |  |  |  | Ebene +1 | 1 | Ne | (7150-36+764+100)/1000- | 2.07.01_G1_45 | 20 | 3.75 | 1166Rau0000033536
WUN-H2-E01-032 | H2 Ebene +1 | Wäsche rein | R | N | NUF | Ebene +1 | 1 | Ne | (7150-36+764+100)/1000- | 2.07.01_G1_42 | 8 | 3.75 | 1166Rau0000033451
WUN-H2-E01-029 | H2 Ebene +1 | EDV | R | TF | NUF | Ebene +1 | 1 | Ne | (7150-36+764+100)/1000- | ELT | 7.5 | 3.75 | 1166Rau0000033418
WUN-H2-E01-026 | H2 Ebene +1 | Lager Fixierbett |  |  |  | Ebene +1 | 1 | Ne | (7150-36+764+100)/1000- | 2.07.01_G1_34 | 4 | 3.75 | 1166Rau0000033385
WUN-H2-E01-038 | H2 Ebene +1 | AR unrein | R | N | NUF | Ebene +1 | 1 | So | (7150-36+764+100)/1000- | 2.07.01_G1_41 | 6 | 3.75 | 1166Rau0000033462 | AllplanAttributes - ash R_Verweis Wandansicht: 2020; Text5: temporär
WUN-H2-E01-039 | H2 Ebene +1 | Stationsbad | R | N | NUF | Ebene +1 | 1 | WC | 6.250000 | 2.07.01_G1_40 | 16 | 3.75 | 1166Rau0000033525 | AllplanAttributes - ash R_Verweis Wandansicht: 2023
WUN-H2-E01-030 | H2 Ebene +1 | WC Pers. | R | N | NUF | Ebene +1 | 1 | WC | (7150-36+764+100)/1000- | 2.07.01_G1_56 | 3.5 | 3.75 | 1166Rau0000033429 | AllplanAttributes - Text3: Sanitärraum
WUN-H2-E01-031 | H2 Ebene +1 | WC Pers. | R | N | NUF | Ebene +1 | 1 | WC | (7150-36+764+100)/1000- | 2.07.01_G1_57 | 3.5 | 3.75 | 1166Rau0000033440 | AllplanAttributes - Status: Neubau; Text3: Sanitärraum
WUN-H2-E01-007 | H2 Ebene +1 | Gespräch | R | N | NUF | Ebene +1 | 1 | So | 7.150000 | 2.07.01_G1_55 | 16 | 3.75 | 1166Rau0000033170 | AllplanAttributes - ash R_Verweis Wandansicht: 2030; Text5: ja
WUN-H2-E01-009 | H2 Ebene +1 | U/B-Raum | R | N | NUF | Ebene +1 | 1 | Un | 6.250000 | 1.12.02_G1_03 | 14 | 3.75 | 1166Rau0000033196 | AllplanAttributes - ash R_Verweis Wandansicht: 2016; Text5: nein
WUN-H2-E01-067 | H2 Ebene +1 | U/B-Raum |  |  |  | Ebene +1 | 1 | Un | 6.250000 | 1.12.02_G1_03 | 14 | 3.75 | 1166Rau0000034261 | AllplanAttributes - Text5: nein
WUN-H2-E01-012 | H2 Ebene +1 | Vorraum Krisenzimmer | R | N | NUF | Ebene +1 | 1 | Ne | 6.250000 |  | 0 | 3.75 | 1166Rau0000034690
WUN-H2-E01-064 | H2 Ebene +1 | Vorraum Krisenzimmer | R | N | NUF | Ebene +1 | 1 | Ne | 6.250000 |  | 0 | 3.75 | 1166Rau0000034701
WUN-H2-E01-058 | H2 Ebene +1 | Ergo- / Kunsttherapie | R | N | NUF | Ebene +1 | 1 | So | 7.150000 | 01.12.02_A2_01 | 38 | 3.75 | 1166Rau0000034124
WUN-H2-E01-010 | H2 Ebene +1 | Ruheraum | R | N | NUF | Ebene +1 | 1 | So | 7.150000 | 2.07.01_G1_29 | 16 | 3.75 | 1166Rau0000033207 | AllplanAttributes - ash R_Verweis Wandansicht: 2029; Text3: Ruheraum
WUN-H2-E01-059 | H2 Ebene +1 | Freizeit / Club | R | N | NUF | Ebene +1 | 1 | So | 7.150000 | 2.07.01_A2_31 | 36 | 3.75 | 1166Rau0000034137
WUN-H2-E01-056 | H2 Ebene +1 | Stationsleitung | R | N | NUF | Ebene +1 | 1 | So | 7.150000 | 2.07.01_A2_55 | 16 | 3.75 | 1166Rau0000034098 | AllplanAttributes - Text5: ja
WUN-H2-E01-066 | H2 Ebene +1 | Ruheraum | R | N | NUF | Ebene +1 | 1 | So | 7.150000 | 2.07.01_A2_29 | 16 | 3.75 | 1166Rau0000034248 | AllplanAttributes - Text3: Ruheraum
WUN-H2-E01-064a | H2 Ebene +1 | Krisenzimmer 1-Bett | R | N | NUF | Ebene +1 | 1 | Be | 7.150000 | 2.07.01_A2_25 | 16 | 3.75 | 1166Rau0000042128
WUN-H2-E01-012a | H2 Ebene +1 | Krisenzimmer 1-Bett | R | N | NUF | Ebene +1 | 1 | Be | 7.150000 | 2.07.01_G1_25 | 16 | 3.75 | 1166Rau0000033238 | AllplanAttributes - ash R_Verweis Wandansicht: 2007
WUN-H2-E01-085 | H2 Ebene +1 | Sprechzimmer | R | N | NUF | Ebene +1 | 1 | Bü | 7.150000 | 2.07.01_A2_50 | 16 | 3.75 | 1166Rau0000034342 | AllplanAttributes - Text5: ja
WUN-H2-E01-084 | H2 Ebene +1 | Pause Personal | R | N | NUF | Ebene +1 | 1 | So | 7.150000 | 2.07.01_A2_58 | 14 | 3.75 | 1166Rau0000034718 | AllplanAttributes - Text1: Standardvorgaben Ausstattung nicht erfüllt; Text4: x; Text5: ja; Text3: Pausenraum
WUN-H2-E01-086 | H2 Ebene +1 | Sprechzimmer |  |  |  | Ebene +1 | 1 | Bü | 7.150000 | 2.07.01_A2_52 | 16 | 3.75 | 1166Rau0000034355 | AllplanAttributes - Text5: ja
WUN-H2-E01-082 | H2 Ebene +1 | Sprechzimmer |  |  |  | Ebene +1 | 1 | Bü | 7.150000 | 2.07.01_A2_53 | 16 | 3.75 | 1166Rau0000034316 | AllplanAttributes - Text5: ja
WUN-H2-E01-083 | H2 Ebene +1 | Sprechzimmer | R | N | NUF | Ebene +1 | 1 | Bü | 7.150000 | 2.07.01_A2_51 | 16 | 3.75 | 1166Rau0000034329 | AllplanAttributes - Text5: ja
WUN-H2-E01-055 | H2 Ebene +1 | Speiseraum | R | N | NUF | Ebene +1 | 1 | So | 6.850000 | 2.07.01_A2_30 | 42 | 3.75 | 1166Rau0000034085 | AllplanAttributes - Text1: Anpassung Flucht Traufe Achse O 3.1-3.5; Text4: x
WUN-H2-E01-011 | H2 Ebene +1 | AR rein | R | N | NUF | Ebene +1 | 1 | So | 7.150000 | 2.07.01_G1_35 | 16 | 3.75 | 1166Rau0000033220 | AllplanAttributes - ash R_Verweis Wandansicht: 2018; Text5: ja
WUN-H2-E01-065 | H2 Ebene +1 | AR rein | R | N | NUF | Ebene +1 | 1 | So | 7.150000 | 2.07.01_G1_35 | 16 | 3.75 | 1166Rau0000034235 | AllplanAttributes - Text5: ja
WUN-H2-E01-048 | H2 Ebene +1 | Stationsküche | R | N | NUF | Ebene +1 | 1 | So | 6.850000 | 2.07.01_G1_36 | 16 | 3.75 | 1166Rau0000033792 | AllplanAttributes - ash R_Verweis Wandansicht: 2008
WUN-H2-E01-050 | H2 Ebene +1 | Stationsküche | R | N | NUF | Ebene +1 | 1 | So | 6.850000 | 2.07.01_A2_36 | 16 | 3.75 | 1166Rau0000033816
WUN-H2-E01-076 | H2 Ebene +1 | Entspannungsbad | R | N | NUF | Ebene +1 | 1 | WC | 6.250000 | 2.07.01_A2_41 | 16 | 3.75 | 1166Rau0000034041 | AllplanAttributes - ash R_Verweis Wandansicht: 2021
WUN-H2-E01-001 | H2 Ebene +1 | Schmutzwäsche, Müll | R | B | NUF | Ebene +1 | 1 | Ne | 6.250000 | 2.07.01_G1_43 | 20 | 3.75 | 1166Rau0000033094
WUN-H2-E01-054 | H2 Ebene +1 | AV | R | TF | NUF | Ebene +1 | 1 | Ne | 7.114000 | ELT | 10 | 3.75 | 1166Rau0000034074
WUN-H2-E01-087 | H2 Ebene +1 | AV | R | TF | NUF | Ebene +1 | 1 | Ne | 7.114000 | ELT | 10 | 3.75 | 1166Rau0000034368
WUN-H2-E01-088 | H2 Ebene +1 | SV | R | TF | NUF | Ebene +1 | 1 | Ne | 7.114000 | ELT | 10 | 3.75 | 1166Rau0000034379
WUN-H2-E01-053 | H2 Ebene +1 | SV | R | TF | NUF | Ebene +1 | 1 | Ne | 7.114000 | ELT | 10 | 3.75 | 1166Rau0000034063
WUN-H2-E01-S01 | H2 Ebene +1 | Hausanschluss | R | N | TF | Ebene +1 | 1 | Ne | 7.114000 | Technik | 0 | 3.75 | 1166Rau0000034591
WUN-H2-E01-002 | H2 Ebene +1 | Lager Versorgungsgüter | R | N | NUF | Ebene +1 | 1 | Ne | (7150-36+764+100)/1000- | 2.07.01_A2_44 | 20 | 3.75 | 1166Rau0000033107
WUN-H2-E01-075 | H2 Ebene +1 | Geräte |  |  |  | Ebene +1 | 1 | Ne | (7150-36+764+100)/1000- | 2.07.01_A2_45 | 20 | 3.75 | 1166Rau0000034030
WUN-H2-E01-077 | H2 Ebene +1 | AR unrein |  |  |  | Ebene +1 | 1 | So | (7150-36+764+100)/1000- | 2.07.01_A2_40 | 6 | 3.75 | 1166Rau0000034052 | AllplanAttributes - Text5: temporär
WUN-H2-E01-078 | H2 Ebene +1 | Wäsche rein |  |  |  | Ebene +1 | 1 | Ne | (7150-36+764+100)/1000- | 2.07.01_A2_42 | 8 | 3.75 | 1166Rau0000034272
WUN-H2-E01-081 | H2 Ebene +1 | EDV | R | TF | NUF | Ebene +1 | 1 | Ne | (7150-36+764+100)/1000- | ELT | 7.5 | 3.75 | 1166Rau0000034305
WUN-H2-E01-089 | H2 Ebene +1 | Lager Fixierbett |  |  |  | Ebene +1 | 1 | Ne | (7150-36+764+100)/1000- | 2.07.01_A2_34 | 4 | 3.75 | 1166Rau0000034390
WUN-H2-E01-052 | H2 Ebene +1 | Vorraum WC | R | N | NUF | Ebene +1 | 1 | WC | 6.250000 | 2.07.01_G1_38 | 0 | 3.75 | 1166Rau0000034712 | AllplanAttributes - ash R_Verweis Wandansicht: 2017
WUN-H2-E01-064b | H2 Ebene +1 | WC Krisenzimmer | R | N | NUF | Ebene +1 | 1 | WC | 6.250000 | 2.07.01_A2_27 | 4 | 3.75 | 1166Rau0000034203 | AllplanAttributes - Text3: Patienten
WUN-H2-E01-051 | H2 Ebene +1 | Hauswirtschaftsraum | R | N | NUF | Ebene +1 | 1 | So | 7.150000 | 01.12.02_A2_03 | 14 | 3.75 | 1166Rau0000033829 | AllplanAttributes - ash R_Verweis Wandansicht: 2009
WUN-H2-E01-073 | H2 Ebene +1 | Ruheraum |  |  |  | Ebene +1 | 1 | Be | 6.850000 | 2.11_A2_01 | 25 | 3.75 | 1166Rau0000034163 | AllplanAttributes - ash R_Verweis Wandansicht: 2028
WUN-H2-E01-073 | H2 Ebene +1 | Ruheraum |  |  |  | Ebene +1 | 1 | Be | 6.850000 | 2.11_A2_01 | 25 | 3.75 | 1166Rau0000034150
WUN-H2-E01-073 | H2 Ebene +1 | Ruheraum |  |  |  | Ebene +1 | 1 | Be | 6.850000 | 2.11_A2_01 | 25 | 3.75 | 1166Rau0000033118 | AllplanAttributes - ash R_Verweis Wandansicht: 2026
WUN-H2-E01-073 | H2 Ebene +1 | Ruheraum |  |  |  | Ebene +1 | 1 | Be | 7.150000 | 2.11_A2_01 | 25 | 3.75 | 1166Rau0000042125 | AllplanAttributes - ash R_Verweis Wandansicht: 2006; Text5: ja
WUN-H2-E01-073 | H2 Ebene +1 | Ruheraum |  |  |  | Ebene +1 | 1 | Be | 6.250000 | 2.11_A2_01 | 25 | 3.75 | 1166Rau0000033283 | AllplanAttributes - ash R_Verweis Wandansicht: 2006; Text5: mittelbar
WUN-H2-E01-073 | H2 Ebene +1 | Ruheraum |  |  |  | Ebene +1 | 1 | Be | 6.250000 | 2.11_A2_01 | 25 | 3.75 | 1166Rau0000034222 | AllplanAttributes - Text5: mittelbar
WUN-H2-E01-073 | H2 Ebene +1 | Ruheraum |  |  |  | Ebene +1 | 1 | Be | 7.150000 | 2.11_A2_01 | 25 | 3.75 | 1166Rau0000033131 | AllplanAttributes - ash R_Verweis Wandansicht: 2015
WUN-H2-E01-073 | H2 Ebene +1 | Ruheraum |  |  |  | Ebene +1 | 1 | Be | 7.150000 | 2.11_A2_01 | 25 | 3.75 | 1166Rau0000033144 | AllplanAttributes - ash R_Verweis Wandansicht: 2014
WUN-H2-E01-049 | H2 Ebene +1 | Speisewagen |  |  |  | Ebene +1 | 1 | Ne | 6.250000 | 2.07.01_G1_37 | 4 | 3.75 | 1166Rau0000033805
WUN-H2-E01-F03a | H2 Ebene +1 | Marktplatz | R | B | NUF | Ebene +1 | 1 | Ne | 6.250000 | 2.07.01_G1_31 | 0 | 3.75 | 1166Rau0000034580 | AllplanAttributes - Status: Neubau; ash R_Verweis Wandansicht: 2030
WUN-H2-E01-073 | H2 Ebene +1 | Ruheraum |  |  |  | Ebene +1 | 1 | Be | 6.250000 | 2.11_A2_01 | 25 | 3.75 | 1166Rau0000033275
WUN-H2-E01-062 | H2 Ebene +1 | WC Bes. rsg. | R | B | NUF | Ebene +1 | 1 | WC | 6.250000 | 2.07.01_A2_48 | 6 | 3.75 | 1166Rau0000034176 | AllplanAttributes - Text3: Besucher
WUN-H2-E01-073 | H2 Ebene +1 | Ruheraum |  |  |  | Ebene +1 | 1 | Be | 6.250000 | 2.11_A2_01 | 25 | 3.75 | 1166Rau0000034214
WUN-H2-E01-F09a | H2 Ebene +1 | Marktplatz | R | N | NUF | Ebene +1 | 1 | Ne | 6.250000 | 2.07.01_A2_32 | 16 | 3.75 | 1166Rau0000034564 | AllplanAttributes - Status: Neubau
WUN-H2-E01-008 | H2 Ebene +1 | Speiseraum | R | N | NUF | Ebene +1 | 1 | So | 6.850000 | 2.07.01_G1_30 | 42 | 3.75 | 1166Rau0000033183 | AllplanAttributes - ash R_Verweis Wandansicht: 2019; Text1: Anpassung Flucht Traufe Achse I 3.1-3.5; Text4: x
WUN-H2-E00-F10 | H2 Ebene 0 | Flur | R | N | VF | Ebene 0 | 1 | Ne | 2.500000 | VF | 0 | 0 | 1115Rau0000005072 | AllplanAttributes - Status: Neubau; BauNVO_Anrechnung_auf_GR: 0; BauNVO_Anrechnung_auf_GF: 0; Pset_SpaceCommon - IsExternal: no; HandicapAccessible: no; Pset_SpaceFireSafetyRequirements - FireExit: no; FireRiskFaktor: A; SprinklerProtection: no; Pset_SpaceLightingRequirements - ArtificialLighting: no; Pset_SpaceThermalRequirements - SpaceHumidity: 0; NaturalVentilation: no; AirConditioning: no; SpaceTemperatureMin: 0; SpaceTemperatureMax: 0
WUN-H2-E00-F05 | H2 Ebene 0 | Flur | R | N | VF | Ebene 0 | 1 | Ne | 2.500000 | VF | 0 | 0 | 1115Rau0000005065 | AllplanAttributes - Status: Neubau; BauNVO_Anrechnung_auf_GR: 0; BauNVO_Anrechnung_auf_GF: 0; Pset_SpaceCommon - IsExternal: no; HandicapAccessible: no; Pset_SpaceFireSafetyRequirements - FireExit: no; FireRiskFaktor: A; SprinklerProtection: no; Pset_SpaceLightingRequirements - ArtificialLighting: no; Pset_SpaceThermalRequirements - SpaceHumidity: 0; NaturalVentilation: no; AirConditioning: no; SpaceTemperatureMin: 0; SpaceTemperatureMax: 0
WUN-H2-E00-F06 | H2 Ebene 0 | Flur | R | N | VF | Ebene 0 | 1 | Ne | 3.400000 | VF | 0 | 0 | 1115Rau0000005169 | AllplanAttributes - Status: Neubau; BauNVO_Anrechnung_auf_GR: 0; BauNVO_Anrechnung_auf_GF: 0; ash R_Verweis Wandansicht: 2005; Pset_SpaceCommon - IsExternal: no; HandicapAccessible: no; Pset_SpaceFireSafetyRequirements - FireExit: no; FireRiskFaktor: A; SprinklerProtection: no; Pset_SpaceLightingRequirements - ArtificialLighting: no; Pset_SpaceThermalRequirements - SpaceHumidity: 0; NaturalVentilation: no; AirConditioning: no; SpaceTemperatureMin: 0; SpaceTemperatureMax: 0
WUN-H2-E00-F08 | H2 Ebene 0 | Flur | R | N | VF | Ebene 0 | 1 | Ne | 3.400000 | VF | 0 | 0 | 1115Rau0000005053 | AllplanAttributes - Status: Neubau; BauNVO_Anrechnung_auf_GR: 0; BauNVO_Anrechnung_auf_GF: 0; Pset_SpaceCommon - IsExternal: no; HandicapAccessible: no; Pset_SpaceFireSafetyRequirements - FireExit: no; FireRiskFaktor: A; SprinklerProtection: no; Pset_SpaceLightingRequirements - ArtificialLighting: no; Pset_SpaceThermalRequirements - SpaceHumidity: 0; NaturalVentilation: no; AirConditioning: no; SpaceTemperatureMin: 0; SpaceTemperatureMax: 0
WUN-H2-E00-T04 | H2 Ebene 0 | TH 4 | R | N | VF | Ebene 0 | 1 | Ne | 3.400000 | VF | 0 | 0 | 1115Rau0000005078 | AllplanAttributes - BauNVO_Anrechnung_auf_GR: 0; BauNVO_Anrechnung_auf_GF: 0; ash D_Detailverweis: TRH4; ash D_Plannummer: D1528; Pset_SpaceCommon - IsExternal: no; HandicapAccessible: no; Pset_SpaceFireSafetyRequirements - FireExit: no; FireRiskFaktor: A; SprinklerProtection: no; Pset_SpaceLightingRequirements - ArtificialLighting: no; Pset_SpaceThermalRequirements - SpaceHumidity: 0; NaturalVentilation: no; AirConditioning: no; SpaceTemperatureMin: 0; SpaceTemperatureMax: 0
WUN-H2-E00-T03 | H2 Ebene 0 | TH 3 | R | N | VF | Ebene 0 | 1 | Ne | 3.400000 | VF | 0 | 0 | 1115Rau0000005075 | AllplanAttributes - BauNVO_Anrechnung_auf_GR: 0; BauNVO_Anrechnung_auf_GF: 0; ash D_Detailverweis: TRH3; ash D_Plannummer: D1527; Pset_SpaceCommon - IsExternal: no; HandicapAccessible: no; Pset_SpaceFireSafetyRequirements - FireExit: no; FireRiskFaktor: A; SprinklerProtection: no; Pset_SpaceLightingRequirements - ArtificialLighting: no; Pset_SpaceThermalRequirements - SpaceHumidity: 0; NaturalVentilation: no; AirConditioning: no; SpaceTemperatureMin: 0; SpaceTemperatureMax: 0
WUN-H2-E00-F01 | H2 Ebene 0 | Foyer | R | N | VF | Ebene 0 | 1 | Ne | 2.750000 | VF | 0 | 0 | 1115Rau0000005189 | AllplanAttributes - Status: Neubau; BauNVO_Anrechnung_auf_GR: 0; BauNVO_Anrechnung_auf_GF: 0; Pset_SpaceCommon - IsExternal: no; HandicapAccessible: no; Pset_SpaceFireSafetyRequirements - FireExit: no; FireRiskFaktor: A; SprinklerProtection: no; Pset_SpaceLightingRequirements - ArtificialLighting: no; Pset_SpaceThermalRequirements - SpaceHumidity: 0; NaturalVentilation: no; AirConditioning: no; SpaceTemperatureMin: 0; SpaceTemperatureMax: 0
WUN-H2-E00-A01 | H2 Ebene 0 | A2 | R | N | VF | Ebene 0 | 1 | Ne | 3.400000 | VF | 0 | 0 | 1115Rau0000005062 | AllplanAttributes - Status: Neubau; BauNVO_Anrechnung_auf_GR: 0; BauNVO_Anrechnung_auf_GF: 0; ash D_Detailverweis: D1502; ash D_Plannummer: D1501; Pset_SpaceCommon - IsExternal: no; HandicapAccessible: no; Pset_SpaceFireSafetyRequirements - FireExit: no; FireRiskFaktor: A; SprinklerProtection: no; Pset_SpaceLightingRequirements - ArtificialLighting: no; Pset_SpaceThermalRequirements - SpaceHumidity: 0; NaturalVentilation: no; AirConditioning: no; SpaceTemperatureMin: 0; SpaceTemperatureMax: 0
WUN-H2-E00-A02 | H2 Ebene 0 | A1 | R | N | VF | Ebene 0 | 1 | Ne | 3.400000 | VF | 0 | 0 | 1115Rau0000005059 | AllplanAttributes - Status: Neubau; BauNVO_Anrechnung_auf_GR: 0; BauNVO_Anrechnung_auf_GF: 0; ash D_Detailverweis: D1502; ash D_Plannummer: D1501; Pset_SpaceCommon - IsExternal: no; HandicapAccessible: no; Pset_SpaceFireSafetyRequirements - FireExit: no; FireRiskFaktor: A; SprinklerProtection: no; Pset_SpaceLightingRequirements - ArtificialLighting: no; Pset_SpaceThermalRequirements - SpaceHumidity: 0; NaturalVentilation: no; AirConditioning: no; SpaceTemperatureMin: 0; SpaceTemperatureMax: 0
WUN-H2-E00-T02 | H2 Ebene 0 | TH 2 | R | N | VF | Ebene 0 | 1 | Ne | 3.400000 | VF | 0 | 0 | 1115Rau0000005069 | AllplanAttributes - BauNVO_Anrechnung_auf_GR: 0; BauNVO_Anrechnung_auf_GF: 0; ash D_Detailverweis: TRH2; ash D_Plannummer: D1526; ash R_Verweis Wandansicht: 1538; Pset_SpaceCommon - IsExternal: no; HandicapAccessible: no; Pset_SpaceFireSafetyRequirements - FireExit: no; FireRiskFaktor: A; SprinklerProtection: no; Pset_SpaceLightingRequirements - ArtificialLighting: no; Pset_SpaceThermalRequirements - SpaceHumidity: 0; NaturalVentilation: no; AirConditioning: no; SpaceTemperatureMin: 0; SpaceTemperatureMax: 0
WUN-H2-E00-F02 | H2 Ebene 0 | Flur | R | N | VF | Ebene 0 | 1 | Ne | 2.650000 | VF | 0 | 0 | 1115Rau0000005163 | AllplanAttributes - Status: Neubau; BauNVO_Anrechnung_auf_GR: 0; BauNVO_Anrechnung_auf_GF: 0; ash D_Detailverweis: SC; ash D_Plannummer: D749; Pset_SpaceCommon - IsExternal: no; HandicapAccessible: no; Pset_SpaceFireSafetyRequirements - FireExit: no; FireRiskFaktor: A; SprinklerProtection: no; Pset_SpaceLightingRequirements - ArtificialLighting: no; Pset_SpaceThermalRequirements - SpaceHumidity: 0; NaturalVentilation: no; AirConditioning: no; SpaceTemperatureMin: 0; SpaceTemperatureMax: 0
WUN-H2-E00-F03 | H2 Ebene 0 | Flur | R | N | VF | Ebene 0 | 1 | Ne | 3.400000 | VF | 0 | 0 | 1115Rau0000005181 | AllplanAttributes - Status: Neubau; BauNVO_Anrechnung_auf_GR: 0; BauNVO_Anrechnung_auf_GF: 0; Pset_SpaceCommon - IsExternal: no; HandicapAccessible: no; Pset_SpaceFireSafetyRequirements - FireExit: no; FireRiskFaktor: A; SprinklerProtection: no; Pset_SpaceLightingRequirements - ArtificialLighting: no; Pset_SpaceThermalRequirements - SpaceHumidity: 0; NaturalVentilation: no; AirConditioning: no; SpaceTemperatureMin: 0; SpaceTemperatureMax: 0
WUN-H2-E00-F07 | H2 Ebene 0 | Flur | R | N | VF | Ebene 0 | 1 | Ne | 3.400000 | VF | 0 | 0 | 1115Rau0000005220 | AllplanAttributes - Status: Neubau; BauNVO_Anrechnung_auf_GR: 0; BauNVO_Anrechnung_auf_GF: 0; Pset_SpaceCommon - IsExternal: no; HandicapAccessible: no; Pset_SpaceFireSafetyRequirements - FireExit: no; FireRiskFaktor: A; SprinklerProtection: no; Pset_SpaceLightingRequirements - ArtificialLighting: no; Pset_SpaceThermalRequirements - SpaceHumidity: 0; NaturalVentilation: no; AirConditioning: no; SpaceTemperatureMin: 0; SpaceTemperatureMax: 0
WUN-H2-E00-F11 | H2 Ebene 0 | Flur | R | N | VF | Ebene 0 | 1 | Ne | 3.100000 | VF | 0 | 0 | 1115Rau0000005201 | AllplanAttributes - Status: Neubau; BauNVO_Anrechnung_auf_GR: 0; BauNVO_Anrechnung_auf_GF: 0; Pset_SpaceCommon - IsExternal: no; HandicapAccessible: no; Pset_SpaceFireSafetyRequirements - FireExit: no; FireRiskFaktor: A; SprinklerProtection: no; Pset_SpaceLightingRequirements - ArtificialLighting: no; Pset_SpaceThermalRequirements - SpaceHumidity: 0; NaturalVentilation: no; AirConditioning: no; SpaceTemperatureMin: 0; SpaceTemperatureMax: 0
WUN-H2-E00-F09 | H2 Ebene 0 | Flur | R | N | VF | Ebene 0 | 1 | Ne | 3.100000 | VF | 0 | 0 | 1115Rau0000005223 | AllplanAttributes - Status: Neubau; BauNVO_Anrechnung_auf_GR: 0; BauNVO_Anrechnung_auf_GF: 0; Pset_SpaceCommon - IsExternal: no; HandicapAccessible: no; Pset_SpaceFireSafetyRequirements - FireExit: no; FireRiskFaktor: A; SprinklerProtection: no; Pset_SpaceLightingRequirements - ArtificialLighting: no; Pset_SpaceThermalRequirements - SpaceHumidity: 0; NaturalVentilation: no; AirConditioning: no; SpaceTemperatureMin: 0; SpaceTemperatureMax: 0
WUN-H2-E00-F04 | H2 Ebene 0 | Flur | R | N | VF | Ebene 0 | 1 | Ne | 3.100000 | VF | 0 | 0 | 1115Rau0000005119 | AllplanAttributes - Status: Neubau; BauNVO_Anrechnung_auf_GR: 0; BauNVO_Anrechnung_auf_GF: 0; Pset_SpaceCommon - IsExternal: no; HandicapAccessible: no; Pset_SpaceFireSafetyRequirements - FireExit: no; FireRiskFaktor: A; SprinklerProtection: no; Pset_SpaceLightingRequirements - ArtificialLighting: no; Pset_SpaceThermalRequirements - SpaceHumidity: 0; NaturalVentilation: no; AirConditioning: no; SpaceTemperatureMin: 0; SpaceTemperatureMax: 0
WUN-H2-E00-T01a | H2 Ebene 0 | Eingangsbereich | R | N | VF | Ebene 0 | 1 | Ne | 2.750000 | VF | 0 | 0 | 1115Rau0000005147 | AllplanAttributes - BauNVO_Anrechnung_auf_GR: 0; BauNVO_Anrechnung_auf_GF: 0; Text1: Umbenennung_Windfang; Pset_SpaceCommon - IsExternal: no; HandicapAccessible: no; Pset_SpaceFireSafetyRequirements - FireExit: no; FireRiskFaktor: A; SprinklerProtection: no; Pset_SpaceLightingRequirements - ArtificialLighting: no; Pset_SpaceThermalRequirements - SpaceHumidity: 0; NaturalVentilation: no; AirConditioning: no; SpaceTemperatureMin: 0; SpaceTemperatureMax: 0
WUN-H2-E00-F07 | H2 Ebene 0 | Flur | R | N | VF | Ebene 0 | 1 | Ne | 3.400000 | VF | 0 | 0 | 1115Rau0000005131 | AllplanAttributes - BauNVO_Anrechnung_auf_GR: 0; BauNVO_Anrechnung_auf_GF: 0; ash D_Detailverweis: TRH1; ash D_Plannummer: D1525; Pset_SpaceCommon - IsExternal: no; HandicapAccessible: no; Pset_SpaceFireSafetyRequirements - FireExit: no; FireRiskFaktor: A; SprinklerProtection: no; Pset_SpaceLightingRequirements - ArtificialLighting: no; Pset_SpaceThermalRequirements - SpaceHumidity: 0; NaturalVentilation: no; AirConditioning: no; SpaceTemperatureMin: 0; SpaceTemperatureMax: 0
WUN-H2-E00-S06 | H2 Ebene 0 | Schacht HLS | R | N | TF | Ebene 0 | 1 | Ne | 3.400000 | Technik | 0 | 0 | 1116Rau0000227457 | AllplanAttributes - Status: Neubau
WUN-H2-E00-S03 | H2 Ebene 0 | Schacht warm | R | N | TF | Ebene 0 | 1 | Ne | 3.400000 | Technik | 0 | 0 | 1116Rau0000227352 | AllplanAttributes - Status: Neubau
WUN-H2-E00-S05 | H2 Ebene 0 | Schacht HLS | R | N | TF | Ebene 0 | 1 | Ne | 3.400000 | Technik | 0 | 0 | 1116Rau0000227422 | AllplanAttributes - Status: Neubau
WUN-H2-E00-S07 | H2 Ebene 0 | Schacht HLS | R | N | TF | Ebene 0 | 1 | Ne | 3.400000 | Technik | 0 | 0 | 1116Rau0000227492 | AllplanAttributes - Status: Neubau
WUN-H2-E00-S04 | H2 Ebene 0 | Schacht HLS | R | N | TF | Ebene 0 | 1 | Ne | 3.400000 | Technik | 0 | 0 | 1116Rau0000227387 | AllplanAttributes - Status: Neubau
WUN-H2-E00-S02 | H2 Ebene 0 | Schacht HLS | R | N | TF | Ebene 0 | 1 | Ne | 3.400000 | Technik | 0 | 0 | 1116Rau0000227317 | AllplanAttributes - Status: Neubau; Text1: Schachbreite in LP 5 kleiner
WUN-H2-E00-S09 | H2 Ebene 0 | Schacht HLS | R | N | TF | Ebene 0 | 1 | Ne | 3.400000 | Technik | 0 | 0 | 1116Rau0000227562 | AllplanAttributes - Status: Neubau; Text1: Schachbreite in LP 5 kleiner
WUN-H2-E00-S08 | H2 Ebene 0 | Schacht kalt | R | N | TF | Ebene 0 | 1 | Ne | 3.400000 | Technik | 0 | 0 | 1116Rau0000227527 | AllplanAttributes - Status: Neubau
WUN-H2-E00-F09a | H2 Ebene 0 | Marktplatz | R | N | NUF | Ebene 0 | 1 | Ne | 2.500000 | 2.07.01_A2_32 | 16 | 0 | 1116Rau0000227242 | AllplanAttributes - Status: Neubau
WUN-H2-E00-079 | H2 Ebene 0 | WC Pers. | R | N | NUF | Ebene 0 | 1 | WC | (3400-36+764+100)/1000- | 2.07.01_A2_56 | 3.5 | 0 | 1116Rau0000065726 | AllplanAttributes - Status: Neubau; Text3: Sanitärraum
WUN-H2-E00-080 | H2 Ebene 0 | WC Pers. | R | N | NUF | Ebene 0 | 1 | WC | (3400-36+764+100)/1000- | 2.07.01_A2_57 | 3.5 | 0 | 1116Rau0000065747 | AllplanAttributes - Status: Neubau; Text3: Sanitärraum
WUN-H2-E00-096a | H2 Ebene 0 | Nasszelle EZ |  |  |  | Ebene 0 | 1 | WC | 2.500000 | 2.07.01_A2_10 | 4 | 0 | 1116Rau0000066486 | AllplanAttributes - Status: Neubau
WUN-H2-E00-030 | H2 Ebene 0 | WC Pers. | R | N | NUF | Ebene 0 | 1 | WC | (3400-36+764+100)/1000- | 2.07.01_G1_56 | 3.5 | 0 | 1116Rau0000065744 | AllplanAttributes - Status: Neubau; Text3: Sanitärraum
WUN-H2-E00-063 | H2 Ebene 0 | Dienstraum Pflege | R | N | NUF | Ebene 0 | 1 | Bü | 2.500000 | 2.07.01_A2_32 | 16 | 0 | 1116Rau0000066600 | AllplanAttributes - Status: Neubau; Text5: mittelbar
WUN-H2-E00-F03a | H2 Ebene 0 | Marktplatz | R | B | NUF | Ebene 0 | 1 | Ne | 2.500000 | 2.07.01_G1_31 | 0 | 0 | 1116Rau0000227279 | AllplanAttributes - Status: Neubau; ash R_Verweis Wandansicht: 2030
WUN-H2-E00-009 | H2 Ebene 0 | U/B-Raum | R | N | NUF | Ebene 0 | 1 | Un | 2.500000 | 1.12.02_G1_03 | 14 | 0 | 1116Rau0000066535 | AllplanAttributes - Status: Neubau; ash R_Verweis Wandansicht: 2016; Text5: nein
WUN-H2-E00-077 | H2 Ebene 0 | AR unrein | R | N | NUF | Ebene 0 | 1 | So | (3400-36+764+100)/1000- | 2.07.01_A2_40 | 6 | 0 | 1116Rau0000066261 | AllplanAttributes - Status: Neubau; Text5: temporär
WUN-H2-E00-049 | H2 Ebene 0 | Speisewagen |  |  |  | Ebene 0 | 1 | Ne | 2.500000 | 2.07.01_G1_37 | 4 | 0 | 1116Rau0000065756 | AllplanAttributes - Status: Neubau
WUN-H2-E00-078 | H2 Ebene 0 | Wäsche rein |  |  |  | Ebene 0 | 1 | Ne | (3400-36+764+100)/1000- | 2.07.01_A2_42 | 8 | 0 | 1116Rau0000065720 | AllplanAttributes - Status: Neubau
WUN-H2-E00-019a | H2 Ebene 0 | Nasszelle EZ+ |  |  |  | Ebene 0 | 1 | WC | 2.500000 | 2.07.01_G1_04 | 4 | 0 | 1116Rau0000066378 | AllplanAttributes - Status: Neubau
WUN-H2-E00-047a | H2 Ebene 0 | Nasszelle EZ | R | N | NUF | Ebene 0 | 1 | WC | 2.500000 | 2.07.01_G1_08 | 4 | 0 | 1116Rau0000065735 | AllplanAttributes - Status: Neubau; ash R_Verweis Wandansicht: 2004
WUN-H2-E00-045a | H2 Ebene 0 | Nasszelle DZ | R | N | NUF | Ebene 0 | 1 | WC | 2.500000 | 2.07.01_G1_24 | 4 | 0 | 1116Rau0000065765 | AllplanAttributes - Status: Neubau; ash R_Verweis Wandansicht: 2001
WUN-H2-E00-044a | H2 Ebene 0 | Nasszelle EZ | R | N | NUF | Ebene 0 | 1 | WC | 2.500000 | 2.07.01_G1_10 | 4 | 0 | 1116Rau0000065774 | AllplanAttributes - Status: Neubau; ash R_Verweis Wandansicht: 2002
WUN-H2-E00-043a | H2 Ebene 0 | Nasszelle rsg. | R | N | NUF | Ebene 0 | 1 | WC | 2.500000 | 2.07.01_G1_14 | 6 | 0 | 1116Rau0000065762 | AllplanAttributes - Status: Neubau; ash R_Verweis Wandansicht: 2024
WUN-H2-E00-090a | H2 Ebene 0 | Nasszelle DZ |  |  |  | Ebene 0 | 1 | WC | 2.500000 | 2.07.01_A2_24 | 4 | 0 | 1116Rau0000065816 | AllplanAttributes - Status: Neubau
WUN-H2-E00-092a | H2 Ebene 0 | Nasszelle rsg. | R | N | NUF | Ebene 0 | 1 | WC | 2.500000 | 2.07.01_A2_14 | 6 | 0 | 1116Rau0000065870 | AllplanAttributes - Status: Neubau
WUN-H2-E00-093a | H2 Ebene 0 | Nasszelle EZ | R | N | NUF | Ebene 0 | 1 | WC | 2.500000 | 2.07.01_A2_09 | 4 | 0 | 1116Rau0000065867 | AllplanAttributes - Status: Neubau
WUN-H2-E00-094a | H2 Ebene 0 | Nasszelle DZ |  |  |  | Ebene 0 | 1 | WC | 2.500000 | 2.07.01_A2_22 | 4 | 0 | 1116Rau0000065822 | AllplanAttributes - Status: Neubau
WUN-H2-E00-091a | H2 Ebene 0 | Nasszelle DZ |  |  |  | Ebene 0 | 1 | WC | 2.500000 | 2.07.01_A2_21 | 4 | 0 | 1116Rau0000065819 | AllplanAttributes - Status: Neubau
WUN-H2-E00-095a | H2 Ebene 0 | Nasszelle DZ |  |  |  | Ebene 0 | 1 | WC | 2.500000 | 2.07.01_A2_23 | 4 | 0 | 1116Rau0000065813 | AllplanAttributes - Status: Neubau
WUN-H2-E00-024a | H2 Ebene 0 | Nasszelle DZ |  |  |  | Ebene 0 | 1 | WC | 2.500000 | 2.07.01_G1_23 | 4 | 0 | 1116Rau0000065789 | AllplanAttributes - Status: Neubau
WUN-H2-E00-025a | H2 Ebene 0 | Nasszelle DZ |  |  |  | Ebene 0 | 1 | WC | 2.500000 | 2.07.01_G1_20 | 4 | 0 | 1116Rau0000065795 | AllplanAttributes - Status: Neubau
WUN-H2-E00-046a | H2 Ebene 0 | Nasszelle EZ+ |  |  |  | Ebene 0 | 1 | WC | 2.500000 | 2.07.01_G1_03 | 4 | 0 | 1116Rau0000065771 | AllplanAttributes - Status: Neubau
WUN-H2-E00-023a | H2 Ebene 0 | Nasszelle rsg. | R | N | NUF | Ebene 0 | 1 | WC | 2.500000 | 2.07.01_G1_13 | 6 | 0 | 1116Rau0000065777 | AllplanAttributes - Status: Neubau
WUN-H2-E00-022a | H2 Ebene 0 | Nasszelle EZ | R | N | NUF | Ebene 0 | 1 | WC | 2.500000 | 2.07.01_G1_09 | 4 | 0 | 1116Rau0000065780 | AllplanAttributes - Status: Neubau
WUN-H2-E00-021a | H2 Ebene 0 | Nasszelle DZ |  |  |  | Ebene 0 | 1 | WC | 2.500000 | 2.07.01_G1_22 | 4 | 0 | 1116Rau0000065783 | AllplanAttributes - Status: Neubau
WUN-H2-E00-020a | H2 Ebene 0 | Nasszelle DZ |  |  |  | Ebene 0 | 1 | WC | 2.500000 | 2.07.01_G1_21 | 4 | 0 | 1116Rau0000065786 | AllplanAttributes - Status: Neubau
WUN-H2-E00-042a | H2 Ebene 0 | Bad mit Dusche | R | N | NUF | Ebene 0 | 1 | WC | 2.500000 | 2.11_G1_04 | 4 | 0 | 1116Rau0000065873 | AllplanAttributes - Status: Neubau; ash R_Verweis Wandansicht: 2003
WUN-H2-E00-064b | H2 Ebene 0 | WC Krisenzimmer | R | N | NUF | Ebene 0 | 1 | WC | 2.500000 | 2.07.01_A2_27 | 4 | 0 | 1116Rau0000066444 | AllplanAttributes - Text3: Patienten
WUN-H2-E00-012b | H2 Ebene 0 | WC Krisenzimmer | R | N | NUF | Ebene 0 | 1 | WC | 2.500000 | 2.07.01_G1_27 | 4 | 0 | 1116Rau0000066424 | AllplanAttributes - ash R_Verweis Wandansicht: 2007; Text3: Patienten
WUN-H2-E00-052b | H2 Ebene 0 | WC Pat. | R | N | NUF | Ebene 0 | 1 | WC | 2.500000 | 2.07.01_G1_38 | 3.5 | 0 | 1116Rau0000065696 | AllplanAttributes - ash R_Verweis Wandansicht: 2017; Text3: Patienten
WUN-H2-E00-074a | H2 Ebene 0 | Bad mit Dusche |  |  |  | Ebene 0 | 1 | WC | 2.500000 | 2.11_A2_04 | 4 | 0 | 1116Rau0000065801 | AllplanAttributes - Status: Neubau
WUN-H2-E00-072a | H2 Ebene 0 | Nasszelle rsg. |  |  |  | Ebene 0 | 1 | WC | 2.500000 | 2.07.01_A2_13 | 6 | 0 | 1116Rau0000065807 | AllplanAttributes - Status: Neubau
WUN-H2-E00-071a | H2 Ebene 0 | Nasszelle EZ |  |  |  | Ebene 0 | 1 | WC | 2.500000 | 2.07.01_A2_08 | 4 | 0 | 1116Rau0000065804 | AllplanAttributes - Status: Neubau
WUN-H2-E00-070a | H2 Ebene 0 | Nasszelle DZ |  |  |  | Ebene 0 | 1 | WC | 2.500000 | 2.07.01_A2_20 | 4 | 0 | 1116Rau0000065883 | AllplanAttributes - Status: Neubau
WUN-H2-E00-069a | H2 Ebene 0 | Nasszelle EZ+ |  |  |  | Ebene 0 | 1 | WC | 2.500000 | 2.07.01_A2_03 | 4 | 0 | 1116Rau0000065798 | AllplanAttributes - Status: Neubau
WUN-H2-E00-068a | H2 Ebene 0 | Nasszelle EZ | R | N | NUF | Ebene 0 | 1 | WC | 2.500000 | 2.07.01_A2_10 | 4 | 0 | 1116Rau0000066852 | AllplanAttributes - Status: Neubau
WUN-H2-E00-073a | H2 Ebene 0 | Bad mit Dusche |  |  |  | Ebene 0 | 1 | WC | 2.500000 | 2.11_A2_03 | 4 | 0 | 1116Rau0000065810 | AllplanAttributes - Status: Neubau
WUN-H2-E00-029 | H2 Ebene 0 | EDV | R | TF | NUF | Ebene 0 | 1 | Ne | (3400-36+764+100)/1000- | ELT | 7.5 | 0 | 1116Rau0000065750 | AllplanAttributes - Status: Neubau
WUN-H2-E00-081 | H2 Ebene 0 | EDV | R | TF | NUF | Ebene 0 | 1 | Ne | (3400-36+764+100)/1000- | ELT | 7.5 | 0 | 1116Rau0000065753 | AllplanAttributes - Status: Neubau
WUN-H2-E00-062 | H2 Ebene 0 | WC Bes. rsg. | R | B | NUF | Ebene 0 | 1 | WC | 2.500000 | 2.07.01_A2_48 | 6 | 0 | 1116Rau0000066864 | AllplanAttributes - Text3: Besucher
WUN-H2-E00-041a | H2 Ebene 0 | Bad mit Dusche |  |  |  | Ebene 0 | 1 | WC | 2.500000 | 2.11_G1_03 | 4 | 0 | 1116Rau0000065768 | AllplanAttributes - Status: Neubau
WUN-H2-E00-002 | H2 Ebene 0 | Lager Versorgungsgüter | R | N | NUF | Ebene 0 | 1 | Ne | (3400-36+764+100)/1000- | 2.07.01_A2_44 | 20 | 0 | 1116Rau0000065699 | AllplanAttributes - Status: Neubau
WUN-H2-E00-F03b | H2 Ebene 0 | Marktplatz | R | B | NUF | Ebene 0 | 1 | Ne | 2.500000 | 2.07.01_G1_31 | 0 | 0 | 1116Rau0000066624 | AllplanAttributes - Status: Neubau
WUN-H2-E00-067 | H2 Ebene 0 | U/B-Raum | R | N | NUF | Ebene 0 | 1 | Un | 2.500000 | 1.12.02_G1_03 | 14 | 0 | 1116Rau0000066544 | AllplanAttributes - Status: Neubau; Text5: nein
WUN-H2-E00-012 | H2 Ebene 0 | Vorraum Krisenzimmer | R | N | NUF | Ebene 0 | 1 | Ne | 2.500000 |  | 0 | 0 | 1116Rau0000066636 | AllplanAttributes - Status: Neubau
WUN-H2-E00-064 | H2 Ebene 0 | Vorraum Krisenzimmer | R | N | NUF | Ebene 0 | 1 | Ne | 2.500000 |  | 0 | 0 | 1116Rau0000066768 | AllplanAttributes - Status: Neubau
WUN-H2-E00-F09b | H2 Ebene 0 | Marktplatz | R | N | NUF | Ebene 0 | 1 | Ne | 2.500000 | 2.07.01_A2_32 | 16 | 0 | 1116Rau0000066588 | AllplanAttributes - Status: Neubau
WUN-H2-E00-013 | H2 Ebene 0 | Dienstraum Pflege | R | N | NUF | Ebene 0 | 1 | Bü | 3.400000 | 2.07.01_A2_49 | 24 | 0 | 1116Rau0000066612 | AllplanAttributes - Status: Neubau; ash R_Verweis Wandansicht: 2006; Text5: mittelbar
WUN-H2-E00-076 | H2 Ebene 0 | Entspannungsbad | R | N | NUF | Ebene 0 | 1 | WC | 2.500000 | 2.07.01_A2_41 | 16 | 0 | 1116Rau0000066268 | AllplanAttributes - Status: Neubau; ash R_Verweis Wandansicht: 2021
WUN-H2-E00-040 | H2 Ebene 0 | Geräte | R | N | NUF | Ebene 0 | 1 | Ne | (3400-36+764+100)/1000- | 2.07.01_G1_45 | 20 | 0 | 1116Rau0000065717 | AllplanAttributes - Status: Neubau; ash R_Verweis Wandansicht: 2022
WUN-H2-E00-032 | H2 Ebene 0 | Wäsche rein | R | N | NUF | Ebene 0 | 1 | Ne | (3400-36+764+100)/1000- | 2.07.01_G1_42 | 8 | 0 | 1116Rau0000065714 | AllplanAttributes - Status: Neubau
WUN-H2-E00-031 | H2 Ebene 0 | WC Pers. | R | N | NUF | Ebene 0 | 1 | WC | (3400-36+764+100)/1000- | 2.07.01_G1_57 | 3.5 | 0 | 1116Rau0000065741 | AllplanAttributes - Status: Neubau; Text3: Sanitärraum
WUN-H2-E00-039 | H2 Ebene 0 | Stationsbad | R | N | NUF | Ebene 0 | 1 | WC | 2.500000 | 2.07.01_G1_40 | 16 | 0 | 1116Rau0000066275 | AllplanAttributes - Status: Neubau; ash R_Verweis Wandansicht: 2023
WUN-H2-E00-038 | H2 Ebene 0 | AR unrein | R | N | NUF | Ebene 0 | 1 | So | (3400-36+764+100)/1000- | 2.07.01_G1_41 | 6 | 0 | 1116Rau0000066282 | AllplanAttributes - Status: Neubau; ash R_Verweis Wandansicht: 2020; Text5: temporär
WUN-H2-E00-010 | H2 Ebene 0 | Ruheraum | R | N | NUF | Ebene 0 | 1 | So | 3.400000 | 2.07.01_G1_29 | 16 | 0 | 1116Rau0000066386 | AllplanAttributes - Status: Neubau; ash R_Verweis Wandansicht: 2029; Text3: Ruheraum
WUN-H2-E00-001 | H2 Ebene 0 | Schmutzwäsche, Müll | R | B | NUF | Ebene 0 | 1 | Ne | (3400-36+764+100)/1000- | 2.07.01_G1_43 | 20 | 0 | 1116Rau0000065702 | AllplanAttributes - Status: Neubau
WUN-H2-E00-052 | H2 Ebene 0 | Vorraum WC | R | N | NUF | Ebene 0 | 1 | WC | 2.500000 | 2.07.01_G1_38 | 0 | 0 | 1116Rau0000069152 | AllplanAttributes - ash R_Verweis Wandansicht: 2017
WUN-H2-E00-052a | H2 Ebene 0 | WC Pat. | R | N | NUF | Ebene 0 | 1 | WC | 2.500000 | 2.07.01_G1_39 | 3.5 | 0 | 1116Rau0000065693 | AllplanAttributes - ash R_Verweis Wandansicht: 2017; Text3: Patienten
WUN-H2-E00-026 | H2 Ebene 0 | Lager Fixierbett |  |  |  | Ebene 0 | 1 | Ne | (3400-36+764+100)/1000- | 2.07.01_G1_34 | 4 | 0 | 1116Rau0000065792 | AllplanAttributes - Status: Neubau
WUN-H2-E00-075 | H2 Ebene 0 | Geräte |  |  |  | Ebene 0 | 1 | Ne | (3400-36+764+100)/1000- | 2.07.01_A2_45 | 20 | 0 | 1116Rau0000065723 | AllplanAttributes - Status: Neubau
WUN-H2-E00-089 | H2 Ebene 0 | Lager Fixierbett |  |  |  | Ebene 0 | 1 | Ne | (3400-36+764+100)/1000- | 2.07.01_A2_34 | 4 | 0 | 1116Rau0000065889 | AllplanAttributes - Status: Neubau
WUN-H2-E00-L01 | H2 Ebene 0 | Loggia I | R | N | NUF | Ebene 0 | 0.5 |  | (3320-185+45)/1000- |  | 0 | 0 | 1116Rau0000933946 | AllplanAttributes - Status: Neubau; ash D_Detailverweis: Außen; ash D_Plannummer: D1556
WUN-H2-E00-L02 | H2 Ebene 0 | Loggia II | R | N | NUF | Ebene 0 | 0.5 |  | (3320-185+45)/1000- |  | 0 | 0 | 1116Rau0000933973 | AllplanAttributes - Status: Neubau; ash D_Detailverweis: Außen; ash D_Plannummer: D1555
WUN-H2-E00-037 | H2 Ebene 0 | Sprechzimmer |  |  |  | Ebene 0 | 1 | Bü | 3.400000 | 2.07.01_G1_53 | 16 | 0 | 1116Rau0000066366 | AllplanAttributes - Status: Neubau; Text5: ja
WUN-H2-E00-036 | H2 Ebene 0 | Sprechzimmer |  |  |  | Ebene 0 | 1 | Bü | 3.400000 | 2.07.01_G1_51 | 16 | 0 | 1116Rau0000066684 | AllplanAttributes - Status: Neubau; Text5: ja
WUN-H2-E00-035 | H2 Ebene 0 | Pause Personal | R | N | NUF | Ebene 0 | 1 | So | 3.400000 | 2.07.01_G1_58 | 14 | 0 | 1116Rau0000066687 | AllplanAttributes - Status: Neubau; ash R_Verweis Wandansicht: 2012; Text5: ja; Text3: Pausenraum
WUN-H2-E00-034 | H2 Ebene 0 | Sprechzimmer | R | N | NUF | Ebene 0 | 1 | Bü | 3.400000 | 2.07.01_G1_50 | 16 | 0 | 1116Rau0000066659 | AllplanAttributes - Status: Neubau; Text5: ja
WUN-H2-E00-033 | H2 Ebene 0 | Sprechzimmer | R | N | NUF | Ebene 0 | 1 | Bü | 3.400000 | 2.07.01_G1_52 | 16 | 0 | 1116Rau0000066656 | AllplanAttributes - Status: Neubau; ash R_Verweis Wandansicht: 2010; Text5: ja
WUN-H2-E00-007 | H2 Ebene 0 | Gespräch | R | N | NUF | Ebene 0 | 1 | So | 3.400000 | 2.07.01_G1_55 | 16 | 0 | 1116Rau0000065711 | AllplanAttributes - Status: Neubau; ash R_Verweis Wandansicht: 2030; Text5: ja
WUN-H2-E00-005 | H2 Ebene 0 | Ergo- / Kunsttherapie | R | N | NUF | Ebene 0 | 1 | So | 3.400000 | 01.12.02_G1_01 | 38 | 0 | 1116Rau0000066394 | AllplanAttributes - Status: Neubau; ash R_Verweis Wandansicht: 2014
WUN-H2-E00-004 | H2 Ebene 0 | Freizeit / Club | R | N | NUF | Ebene 0 | 1 | So | 3.400000 | 2.07.01_G1_31 | 36 | 0 | 1116Rau0000066414 | AllplanAttributes - Status: Neubau; ash R_Verweis Wandansicht: 2015
WUN-H2-E00-011 | H2 Ebene 0 | AR rein | R | N | NUF | Ebene 0 | 1 | So | 3.400000 | 2.07.01_G1_35 | 16 | 0 | 1116Rau0000066472 | AllplanAttributes - Status: Neubau; ash R_Verweis Wandansicht: 2018; Text5: ja
WUN-H2-E00-065 | H2 Ebene 0 | AR rein | R | N | NUF | Ebene 0 | 1 | So | 3.400000 | 2.07.01_G1_35 | 16 | 0 | 1116Rau0000066789 | AllplanAttributes - Status: Neubau; Text5: ja
WUN-H2-E00-066 | H2 Ebene 0 | Ruheraum | R | N | NUF | Ebene 0 | 1 | So | 3.400000 | 2.07.01_A2_29 | 16 | 0 | 1116Rau0000066402 | AllplanAttributes - Status: Neubau; Text3: Ruheraum
WUN-H2-E00-051 | H2 Ebene 0 | Hauswirtschaftsraum | R | N | NUF | Ebene 0 | 1 | So | 3.400000 | 01.12.02_A2_03 | 14 | 0 | 1116Rau0000065690 | AllplanAttributes - Status: Neubau; ash R_Verweis Wandansicht: 2009
WUN-H2-E00-012a | H2 Ebene 0 | Krisenzimmer 1-Bett | R | N | NUF | Ebene 0 | 1 | Be | 3.400000 | 2.07.01_G1_25 | 16 | 0 | 1116Rau0000066462 | AllplanAttributes - Status: Neubau; ash R_Verweis Wandansicht: 2007
WUN-H2-E00-013a | H2 Ebene 0 | Backoffice | R | N | NUF | Ebene 0 | 1 | Bü | 3.400000 | 2.07.01_A2_49 | 24 | 0 | 1116Rau0000066441 | AllplanAttributes - Status: Neubau; ash R_Verweis Wandansicht: 2006; Text5: ja
WUN-H2-E00-064a | H2 Ebene 0 | Krisenzimmer 1-Bett | R | N | NUF | Ebene 0 | 1 | Be | 3.400000 | 2.07.01_A2_25 | 16 | 0 | 1116Rau0000066771 | AllplanAttributes - Status: Neubau
WUN-H2-E00-058 | H2 Ebene 0 | Ergo- / Kunsttherapie | R | N | NUF | Ebene 0 | 1 | So | 3.400000 | 01.12.02_A2_01 | 38 | 0 | 1116Rau0000066409 | AllplanAttributes - Status: Neubau
WUN-H2-E00-059 | H2 Ebene 0 | Freizeit / Club | R | N | NUF | Ebene 0 | 1 | So | 3.400000 | 2.07.01_A2_31 | 36 | 0 | 1116Rau0000066828 | AllplanAttributes - Status: Neubau
WUN-H2-E00-056 | H2 Ebene 0 | Stationsleitung | R | N | NUF | Ebene 0 | 1 | So | 3.400000 | 2.07.01_A2_55 | 16 | 0 | 1116Rau0000066811 | AllplanAttributes - Status: Neubau; Text5: ja
WUN-H2-E00-086 | H2 Ebene 0 | Sprechzimmer |  |  |  | Ebene 0 | 1 | Bü | 3.400000 | 2.07.01_A2_52 | 16 | 0 | 1116Rau0000066734 | AllplanAttributes - Status: Neubau; Text5: ja
WUN-H2-E00-085 | H2 Ebene 0 | Sprechzimmer |  |  |  | Ebene 0 | 1 | Bü | 3.400000 | 2.07.01_A2_50 | 16 | 0 | 1116Rau0000066731 | AllplanAttributes - Status: Neubau; Text5: ja
WUN-H2-E00-084 | H2 Ebene 0 | Pause Personal | R | N | NUF | Ebene 0 | 1 | So | 3.400000 | 2.07.01_A2_58 | 14 | 0 | 1116Rau0000066737 | AllplanAttributes - Status: Neubau; Text5: ja; Text3: Pausenraum
WUN-H2-E00-083 | H2 Ebene 0 | Sprechzimmer | R | N | NUF | Ebene 0 | 1 | Bü | 3.400000 | 2.07.01_A2_51 | 16 | 0 | 1116Rau0000066707 | AllplanAttributes - Status: Neubau; Text5: ja
WUN-H2-E00-082 | H2 Ebene 0 | Sprechzimmer |  |  |  | Ebene 0 | 1 | Bü | 3.400000 | 2.07.01_A2_53 | 16 | 0 | 1116Rau0000066364 | AllplanAttributes - Status: Neubau; Text5: ja
WUN-H2-E00-090 | H2 Ebene 0 | Doppelzimmer | R | N | NUF | Ebene 0 | 1 | Be | 3.150000 | 2.07.01_A2_19 | 26 | 0 | 1116Rau0000066333 | AllplanAttributes - Status: Neubau; Text1: Achtung Wand in LP 5 in Achse um 2,5cm nach rechts verschieben!!!
WUN-H2-E00-042 | H2 Ebene 0 | Ruheraum | R | N | NUF | Ebene 0 | 1 | Be | 3.150000 | 2.11_G1_02 | 25 | 0 | 1116Rau0000065849 | AllplanAttributes - Status: Neubau; ash R_Verweis Wandansicht: 2003
WUN-H2-E00-096 | H2 Ebene 0 | Einzelzimmer mit Zustelloption | R | B | NUF | Ebene 0 | 1 | Be | 3.150000 | 2.07.01_A2_07 | 25 | 0 | 1116Rau0000066512 | AllplanAttributes - Status: Neubau
WUN-H2-E00-074 | H2 Ebene 0 | Ruheraum | R | N | NUF | Ebene 0 | 1 | Be | 3.150000 | 2.11_A2_02 | 25 | 0 | 1116Rau0000065852 | AllplanAttributes - Status: Neubau; Text1: Achtung Wand in LP 5 in Achse um 2,5cm nach rechts verschieben!!!
WUN-H2-E00-046 | H2 Ebene 0 | Einzelzimmer mit Zustelloption |  |  |  | Ebene 0 | 1 | Be | 3.150000 | 2.07.01_G1_01 | 25 | 0 | 1116Rau0000065834 | AllplanAttributes - Status: Neubau; ash R_Verweis Wandansicht: 2010
WUN-H2-E00-093 | H2 Ebene 0 | Einzelzimmer | R | N | NUF | Ebene 0 | 1 | Be | 3.150000 | 2.07.01_A2_06 | 20 | 0 | 1116Rau0000066330 | AllplanAttributes - Status: Neubau
WUN-H2-E00-094 | H2 Ebene 0 | Doppelzimmer | R | N | NUF | Ebene 0 | 1 | Be | 3.150000 | 2.07.01_A2_17 | 26 | 0 | 1116Rau0000066342 | AllplanAttributes - Status: Neubau; Text1: Achtung Wand in LP 5 in Achse um 2,5cm nach links verschieben!!!
WUN-H2-E00-047 | H2 Ebene 0 | Einzelzimmer Adipositas | R | N | NUF | Ebene 0 | 1 | Be | 3.150000 | 2.07.01_G1_05 | 20 | 0 | 1116Rau0000066574 | AllplanAttributes - Status: Neubau; ash R_Verweis Wandansicht: 2004
WUN-H2-E00-045 | H2 Ebene 0 | Doppelzimmer | R | N | NUF | Ebene 0 | 1 | Be | 3.150000 | 2.07.01_G1_19 | 26 | 0 | 1116Rau0000065831 | AllplanAttributes - Status: Neubau; ash R_Verweis Wandansicht: 2001
WUN-H2-E00-044 | H2 Ebene 0 | Einzelzimmer | R | N | NUF | Ebene 0 | 1 | Be | 3.150000 | 2.07.01_G1_07 | 20 | 0 | 1116Rau0000065828 | AllplanAttributes - Status: Neubau; ash R_Verweis Wandansicht: 2002
WUN-H2-E00-043 | H2 Ebene 0 | Rollstuhlgerechtes Doppelzimmer | R | N | NUF | Ebene 0 | 1 | Be | 3.150000 | 2.07.01_G1_12 | 26 | 0 | 1116Rau0000065825 | AllplanAttributes - Status: Neubau; ash R_Verweis Wandansicht: 2024
WUN-H2-E00-068 | H2 Ebene 0 | Einzelzimmer Adipositas | R | N | NUF | Ebene 0 | 1 | Be | 3.150000 | 2.07.01_A2_07 | 20 | 0 | 1116Rau0000066838 | AllplanAttributes - Status: Neubau
WUN-H2-E00-069 | H2 Ebene 0 | Einzelzimmer mit Zustelloption | R | N | NUF | Ebene 0 | 1 | Be | 3.150000 | 2.07.01_A2_01 | 25 | 0 | 1116Rau0000065846 | AllplanAttributes - Status: Neubau; Text1: Achtung Wand in LP 5 in Achse um 2,5cm nach links verschieben!!!
WUN-H2-E00-070 | H2 Ebene 0 | Doppelzimmer | R | N | NUF | Ebene 0 | 1 | Be | 3.150000 | 2.07.01_A2_15 | 26 | 0 | 1116Rau0000065886 | AllplanAttributes - Status: Neubau; Text1: Achtung Wand in LP 5 in Achse um 2,5cm nach links verschieben!!!
WUN-H2-E00-071 | H2 Ebene 0 | Einzelzimmer |  |  |  | Ebene 0 | 1 | Be | 3.150000 | 2.07.01_A2_05 | 20 | 0 | 1116Rau0000065843 | AllplanAttributes - Status: Neubau
WUN-H2-E00-072 | H2 Ebene 0 | Rollstuhlgerechtes Doppelzimmer |  |  |  | Ebene 0 | 1 | Be | 3.150000 | 2.07.01_A2_11 | 26 | 0 | 1116Rau0000065840 | AllplanAttributes - Status: Neubau
WUN-H2-E00-073 | H2 Ebene 0 | Ruheraum |  |  |  | Ebene 0 | 1 | Be | 3.150000 | 2.11_A2_01 | 25 | 0 | 1116Rau0000065855 | AllplanAttributes - Status: Neubau
WUN-H2-E00-091 | H2 Ebene 0 | Doppelzimmer |  |  |  | Ebene 0 | 1 | Be | 3.150000 | 2.07.01_A2_16 | 26 | 0 | 1116Rau0000066336 | AllplanAttributes - Status: Neubau
WUN-H2-E00-092 | H2 Ebene 0 | Rollstuhlgerechtes Doppelzimmer | R | N | NUF | Ebene 0 | 1 | Be | 3.150000 | 2.07.01_A2_12 | 26 | 0 | 1116Rau0000066339 | AllplanAttributes - Status: Neubau; Text1: Achtung Wand in LP 5 in Achse um 2,5cm nach rechts verschieben!!!
WUN-H2-E00-095 | H2 Ebene 0 | Doppelzimmer | R | N | NUF | Ebene 0 | 1 | Be | 3.150000 | 2.07.01_A2_18 | 26 | 0 | 1116Rau0000066498 | AllplanAttributes - Status: Neubau; Text1: Achtung Wand in LP 5 in Achse um 2,5cm nach links verschieben!!!
WUN-H2-E00-025 | H2 Ebene 0 | Doppelzimmer |  |  |  | Ebene 0 | 1 | Be | 3.150000 | 2.07.01_G1_18 | 26 | 0 | 1116Rau0000066303 | AllplanAttributes - Status: Neubau
WUN-H2-E00-024 | H2 Ebene 0 | Doppelzimmer |  |  |  | Ebene 0 | 1 | Be | 3.150000 | 2.07.01_G1_17 | 26 | 0 | 1116Rau0000066300 | AllplanAttributes - Status: Neubau
WUN-H2-E00-022 | H2 Ebene 0 | Einzelzimmer | R | N | NUF | Ebene 0 | 1 | Be | 3.150000 | 2.07.01_G1_06 | 20 | 0 | 1116Rau0000066291 | AllplanAttributes - Status: Neubau
WUN-H2-E00-021 | H2 Ebene 0 | Doppelzimmer |  |  |  | Ebene 0 | 1 | Be | 3.150000 | 2.07.01_G1_16 | 26 | 0 | 1116Rau0000066297 | AllplanAttributes - Status: Neubau
WUN-H2-E00-020 | H2 Ebene 0 | Doppelzimmer | R | B | NUF | Ebene 0 | 1 | Be | 3.150000 | 2.07.01_G1_15 | 26 | 0 | 1116Rau0000066294 | AllplanAttributes - Status: Neubau
WUN-H2-E00-019 | H2 Ebene 0 | Einzelzimmer mit Zustelloption | R | N | NUF | Ebene 0 | 1 | Be | 3.150000 | 2.07.01_G1_05 | 25 | 0 | 1116Rau0000066560 | AllplanAttributes - Status: Neubau
WUN-H2-E00-041 | H2 Ebene 0 | Ruheraum | R | N | NUF | Ebene 0 | 1 | Be | 3.150000 | 2.11_G1_01 | 25 | 0 | 1116Rau0000065759 | AllplanAttributes - Status: Neubau
WUN-H2-E00-023 | H2 Ebene 0 | Rollstuhlgerechtes Doppelzimmer | R | N | NUF | Ebene 0 | 1 | Be | 3.150000 | 2.07.01_G1_11 | 26 | 0 | 1116Rau0000066288 | AllplanAttributes - Status: Neubau
WUN-H2-E00-060 | H2 Ebene 0 | Aufenthalt / Besucher |  |  |  | Ebene 0 | 1 | So | 3.100000 | 2.07.01_A2_32 | 16 | 0 | 1116Rau0000066527 | AllplanAttributes - Status: Neubau
WUN-H2-E00-061 | H2 Ebene 0 | DR Therapeut | R | N | NUF | Ebene 0 | 1 | Bü | 3.100000 | 01.12.02_A2_05 | 16 | 0 | 1116Rau0000066520 | AllplanAttributes - Status: Neubau; ash R_Verweis Wandansicht: 2028
WUN-H2-E00-003 | H2 Ebene 0 | Aufenthalt / Besucher | R | N | NUF | Ebene 0 | 1 | So | 3.100000 | 2.07.01_G1_32 | 16 | 0 | 1116Rau0000065705 | AllplanAttributes - Status: Neubau; ash R_Verweis Wandansicht: 2026
WUN-H2-E00-008 | H2 Ebene 0 | Speiseraum | R | N | NUF | Ebene 0 | 1 | So | 3.100000 | 2.07.01_G1_30 | 42 | 0 | 1116Rau0000065732 | AllplanAttributes - Status: Neubau; ash R_Verweis Wandansicht: 2019; Text1: Anpassung Flucht Traufe Achse I 3.1-3.5
WUN-H2-E00-048 | H2 Ebene 0 | Stationsküche | R | N | NUF | Ebene 0 | 1 | So | 3.100000 | 2.07.01_G1_36 | 16 | 0 | 1116Rau0000065864 | AllplanAttributes - Status: Neubau; ash R_Verweis Wandansicht: 2008
WUN-H2-E00-050 | H2 Ebene 0 | Stationsküche | R | N | NUF | Ebene 0 | 1 | So | 3.100000 | 2.07.01_A2_36 | 16 | 0 | 1116Rau0000065837 | AllplanAttributes - Status: Neubau
WUN-H2-E00-055 | H2 Ebene 0 | Speiseraum | R | N | NUF | Ebene 0 | 1 | So | 3.100000 | 2.07.01_A2_30 | 42 | 0 | 1116Rau0000065729 | AllplanAttributes - Status: Neubau; Text1: Anpassung Flucht Traufe Achse O 3.1-3.5
WUN-H2-E00-027 | H2 Ebene 0 | SV | R | TF | NUF | Ebene 0 | 1 | Ne | 3.364000 | ELT | 10 | 0 | 1116Rau0000065876 | AllplanAttributes - Status: Neubau
WUN-H2-E00-028 | H2 Ebene 0 | AV | R | TF | NUF | Ebene 0 | 1 | Ne | 3.364000 | ELT | 10 | 0 | 1116Rau0000065879 | AllplanAttributes - Status: Neubau
WUN-H2-E00-088 | H2 Ebene 0 | SV | R | TF | NUF | Ebene 0 | 1 | Ne | 3.364000 | ELT | 10 | 0 | 1116Rau0000065892 | AllplanAttributes - Status: Neubau
WUN-H2-E00-087 | H2 Ebene 0 | AV | R | TF | NUF | Ebene 0 | 1 | Ne | 3.364000 | ELT | 10 | 0 | 1116Rau0000065895 | AllplanAttributes - Status: Neubau
WUN-H2-E00-054 | H2 Ebene 0 | AV |  | TF |  | Ebene 0 | 1 | Ne | 3.364000 | ELT | 10 | 0 | 1116Rau0000065861 | AllplanAttributes - Status: Neubau
WUN-H2-E00-053 | H2 Ebene 0 | SV |  | TF |  | Ebene 0 | 1 | Ne | 3.364000 | ELT | 10 | 0 | 1116Rau0000065858 | AllplanAttributes - Status: Neubau
WUN-H2-E00-S01 | H2 Ebene 0 | Hausanschluss | R | N | TF | Ebene 0 | 1 | Ne | 3.364000 | Technik | 0 | 0 | 1116Rau0000065708 | AllplanAttributes - Status: Neubau

# IfcBeam (310)
AllplanAttributes - Abrechnungsart: m³
Pset_BeamCommon - Status: NEW; LoadBearing: yes
Name | In | Material | 2D Interaktion | Gewerk | Ortscode_Geschoßbezeichnung | AllplanAttributes, Material | OKFF | Allright_Bauteil_ID | Objektname | IsExternal | ThermalTransmittance (W/K/m2)
 | H2 Ebene +4/ Dachebene | BS Bekleidung | yes | Zimmer- und Holzbauarbeiten | E00 | BS Bekleidung | 11.25 | 1406Kop0000015304 | Mengenkörper | no | 0 | AllplanAttributes - Material Architektur: Gipsfaserplatten 2-lagig (BSK)
 | H2 Ebene +4/ Dachebene | BS Bekleidung | yes | Zimmer- und Holzbauarbeiten | E00 | BS Bekleidung | 11.25 | 1406Kop0000015842 | Mengenkörper | no | 0 | AllplanAttributes - Material Architektur: Gipsfaserplatten 2-lagig (BSK)
 | H2 Ebene +4/ Dachebene | BS Bekleidung | yes | Zimmer- und Holzbauarbeiten | E00 | BS Bekleidung | 11.25 | 1406Kop0000015303 | Mengenkörper | no | 0 | AllplanAttributes - Material Architektur: Gipsfaserplatten 2-lagig (BSK)
 | H2 Ebene +4/ Dachebene | BS Bekleidung | yes | Zimmer- und Holzbauarbeiten | E00 | BS Bekleidung | 11.25 | 1406Kop0000015305 | Mengenkörper | no | 0 | AllplanAttributes - Material Architektur: Gipsfaserplatten 2-lagig (BSK)
 | H2 Ebene +4/ Dachebene | BS Bekleidung | yes | Zimmer- und Holzbauarbeiten | E00 | BS Bekleidung | 11.25 | 1406Kop0000016032 | Mengenkörper | no | 0 | AllplanAttributes - Material Architektur: Gipsfaserplatten 2-lagig (BSK)
 | H2 Ebene +4/ Dachebene | BS Bekleidung | yes | Zimmer- und Holzbauarbeiten | E00 | BS Bekleidung | 11.25 | 1406Kop0000016031 | Mengenkörper | no | 0 | AllplanAttributes - Material Architektur: Gipsfaserplatten 2-lagig (BSK)
 | H2 Ebene +4/ Dachebene | Firstpfette | yes | Zimmer- und Holzbauarbeiten |  | Firstpfette | 11.25 | 1406Unz0000015316 | Unterzug | no | 0 | AllplanAttributes - Material Statik: BSH GL24c; Positionsnummer_Text: PF13
 | H2 Ebene +4/ Dachebene | Mittelpfette | yes | Zimmer- und Holzbauarbeiten |  | Mittelpfette | 11.25 | 1406Unz0000015347 | Unterzug | no | 0 | AllplanAttributes - Material Statik: BSH GL28c; Positionsnummer_Text: PF18
 | H2 Ebene +4/ Dachebene | Firstpfette | yes | Zimmer- und Holzbauarbeiten |  | Firstpfette | 11.25 | 1406Unz0000015840 | Unterzug | no | 0 | AllplanAttributes - Material Statik: BSH GL24c; Positionsnummer_Text: PF13
 | H2 Ebene +4/ Dachebene | Mittelpfette | yes | Zimmer- und Holzbauarbeiten |  | Mittelpfette | 11.25 | 1406Unz0000015350 | Unterzug | no | 0 | AllplanAttributes - Material Statik: BSH GL24c; Positionsnummer_Text: PF9
 | H2 Ebene +4/ Dachebene | Pfette | yes | Zimmer- und Holzbauarbeiten |  | Pfette | 11.25 | 1406Unz0000016052 | Unterzug | no | 0 | AllplanAttributes - Material Statik: BSH GL24c; Positionsnummer_Text: PF9
 | H2 Ebene +4/ Dachebene | Pfette | yes | Zimmer- und Holzbauarbeiten |  | Pfette | 11.25 | 1406Unz0000016060 | Unterzug | no | 0 | AllplanAttributes - Material Statik: Baubuche GL75; Positionsnummer_Text: PF19
 | H2 Ebene +3 | BS Bekleidung | yes | Zimmer- und Holzbauarbeiten | E00 | BS Bekleidung | 11.25 | 1263Kop0813033142 | Mengenkörper | no | 0 | AllplanAttributes - Material Architektur: Gipsfaserplatten 2-lagig (BSK)
 | H2 Ebene +3 | BS Bekleidung | yes | Zimmer- und Holzbauarbeiten | E00 | BS Bekleidung | 11.25 | 1263Kop0812846022 | Mengenkörper | no | 0 | AllplanAttributes - Material Architektur: Gipsfaserplatten 2-lagig (BSK)
 | H2 Ebene +3 | BS Bekleidung | yes | Zimmer- und Holzbauarbeiten | E00 | BS Bekleidung | 11.25 | 1263Kop0813034442 | Mengenkörper | no | 0 | AllplanAttributes - Material Architektur: Gipsfaserplatten 2-lagig (BSK)
 | H2 Ebene +3 | BS Bekleidung | yes | Zimmer- und Holzbauarbeiten | E00 | BS Bekleidung | 11.25 | 1263Kop0813034829 | Mengenkörper | no | 0 | AllplanAttributes - Material Architektur: Gipsfaserplatten 2-lagig (BSK)
 | H2 Ebene +3 | BS Bekleidung | yes | Zimmer- und Holzbauarbeiten | E00 | BS Bekleidung | 11.25 | 1263Kop0813035293 | Mengenkörper | no | 0 | AllplanAttributes - Material Architektur: Gipsfaserplatten 2-lagig (BSK)
 | H2 Ebene +3 | BS Bekleidung | yes | Zimmer- und Holzbauarbeiten | E00 | BS Bekleidung | 11.25 | 1263Kop0813035312 | Mengenkörper | no | 0 | AllplanAttributes - Material Architektur: Gipsfaserplatten 2-lagig (BSK)
 | H2 Ebene +3 | STB | yes | Betonarbeiten |  | STB | 11.25 | 1263Unz0812784682 | Überzug | no | 0 | AllplanAttributes - Positionsnummer_Text: PF9
 | H2 Ebene +3 | STB | yes | Betonarbeiten |  | STB | 11.25 | 1263Unz0812784678 | Überzug | no | 0 | AllplanAttributes - Positionsnummer_Text: PF9
 | H2 Ebene +3 | Firstpfette | yes | Zimmer- und Holzbauarbeiten |  | Firstpfette | 11.25 | 1263Unz0813034827 | Unterzug | no | 0 | AllplanAttributes - Material Statik: BSH GL24c; Positionsnummer_Text: PF9
 | H2 Ebene +3 | Firstpfette | yes | Zimmer- und Holzbauarbeiten |  | Firstpfette | 11.25 | 1263Unz0813033143 | Unterzug | no | 0 | AllplanAttributes - Material Statik: BSH GL24c; Positionsnummer_Text: PF9
 | H2 Ebene +3 | STB | yes | Betonarbeiten |  | STB | 11.25 | 1263Unz0812784670 | Überzug | no | 0 | AllplanAttributes - Positionsnummer_Text: PF9
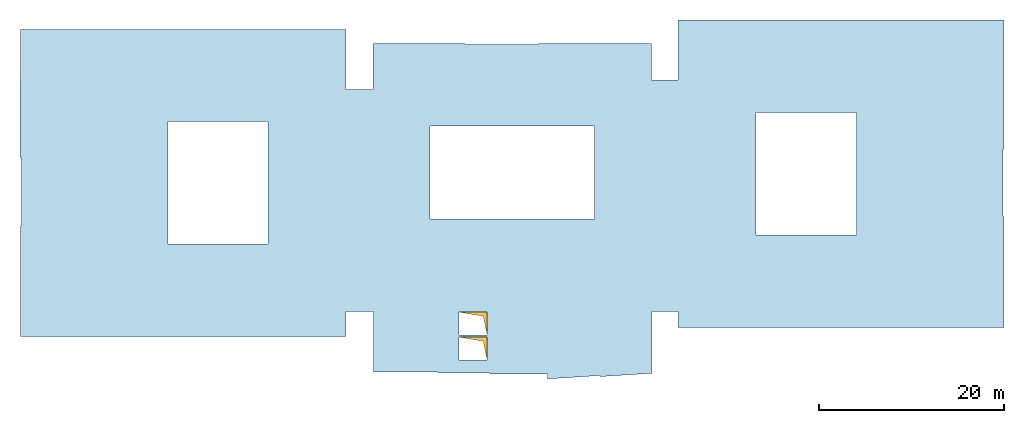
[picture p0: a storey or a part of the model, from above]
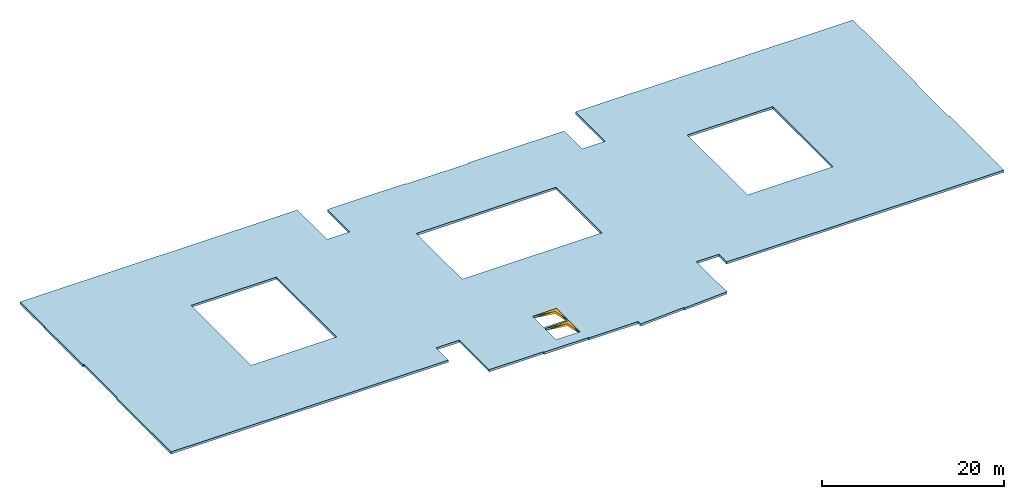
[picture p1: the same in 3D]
Properties of the parts of a building model (IFC4), part 3 of 80

# IfcBeam (310)
Name | In | Material | 2D Interaktion | Gewerk | Ortscode_Geschoßbezeichnung | AllplanAttributes, Material | OKFF | Allright_Bauteil_ID | Objektname | IsExternal | ThermalTransmittance (W/K/m2)
 | H2 Ebene +3 | Pfette 6 | yes | Zimmer- und Holzbauarbeiten |  | Pfette 6 | 11.25 | 1263Unz0812776337 | Unterzug | no | 0 | AllplanAttributes - Material Statik: BSH GL24c; Positionsnummer_Text: PF9
 | H2 Ebene +3 | Pfette 6 | yes | Zimmer- und Holzbauarbeiten |  | Pfette 6 | 11.25 | 1263Unz0813035291 | Unterzug | no | 0 | AllplanAttributes - Material Statik: BSH GL24c; Positionsnummer_Text: PF9
 | H2 Ebene +3 | Pfette 10 | yes | Zimmer- und Holzbauarbeiten |  | Pfette 10 | 11.25 | 1263Unz0812776569 | Unterzug | no | 0 | AllplanAttributes - Material Statik: BSH GL24c; Positionsnummer_Text: PF9
FS-Vorhang | H2 Ebene +3 |  | no | Zusatzgewerk Kunde |  |  | 0 | 1263Unz0812964349 | Brandschutzvorhang | no | 0 | AllplanAttributes - Text1: S200 C2; Bezeichnung: FS-Vorhang; Rauchschutz: yes; Selbstschließend: yes; Sicherheitsklasse: -; ash T_Tür-Nr.: FS-Vorhang; ash T_Raum zugehörigkeit: BS; Pset_BeamCommon - FireRating: EI2 60
 | H2 Ebene +3 | STB | yes | Betonarbeiten |  | STB | 11.25 | 1263Unz0812784662 | Überzug | no | 0 | AllplanAttributes - Positionsnummer_Text: PF9
 | H2 Ebene +3 | Pfette 10 | yes | Zimmer- und Holzbauarbeiten |  | Pfette 10 | 11.25 | 1263Unz0813035310 | Unterzug | no | 0 | AllplanAttributes - Material Statik: BSH GL24c; Positionsnummer_Text: PF9
 | H2 Ebene +3 | STB | yes | Betonarbeiten |  | STB | 11.25 | 1263Unz0812784650 | Überzug | no | 0 | AllplanAttributes - Positionsnummer_Text: PF9
 | H2 Ebene +3 | STB | yes | Betonarbeiten |  | STB | 11.25 | 1263Unz0812784666 | Überzug | no | 0 | AllplanAttributes - Positionsnummer_Text: PF9
 | H2 Ebene +3 | STB | yes | Betonarbeiten |  | STB | 11.25 | 1263Unz0812784656 | Überzug | no | 0 | AllplanAttributes - Positionsnummer_Text: PF9
 | H2 Ebene +3 | STB | yes | Betonarbeiten |  | STB | 11.25 | 1263Unz0812923011 | Überzug | no | 0 | AllplanAttributes - Positionsnummer_Text: U19
 | H2 Ebene +2 | BS Bekleidung | yes | Zimmer- und Holzbauarbeiten | E00 | BS Bekleidung | 7.5 | 1205Kop0000268305 | Mengenkörper | no | 0 | AllplanAttributes - Material Architektur: Gipsfaserplatten 2-lagig (BSK); ash D_Detailverweis: <undefiniert>
 | H2 Ebene +2 | BS Bekleidung | yes | Zimmer- und Holzbauarbeiten | E00 | BS Bekleidung | 7.5 | 1205Kop0000268344 | Mengenkörper | no | 0 | AllplanAttributes - Material Architektur: Gipsfaserplatten 2-lagig (BSK); ash D_Detailverweis: <undefiniert>
 | H2 Ebene +2 | BS Bekleidung | yes | Zimmer- und Holzbauarbeiten | E00 | BS Bekleidung | 7.5 | 1205Kop0000268383 | Mengenkörper | no | 0 | AllplanAttributes - Material Architektur: Gipsfaserplatten 2-lagig (BSK); ash D_Detailverweis: <undefiniert>
 | H2 Ebene +2 | BS Bekleidung | yes | Zimmer- und Holzbauarbeiten | E00 | BS Bekleidung | 7.5 | 1205Kop0000268422 | Mengenkörper | no | 0 | AllplanAttributes - Material Architektur: Gipsfaserplatten 2-lagig (BSK); ash D_Detailverweis: <undefiniert>
 | H2 Ebene +2 | BS Bekleidung | yes | Zimmer- und Holzbauarbeiten | E00 | BS Bekleidung | 7.5 | 1205Kop0000268461 | Mengenkörper | no | 0 | AllplanAttributes - Material Architektur: Gipsfaserplatten 2-lagig (BSK); ash D_Detailverweis: <undefiniert>
 | H2 Ebene +2 | BS Bekleidung | yes | Zimmer- und Holzbauarbeiten | E00 | BS Bekleidung | 7.5 | 1205Kop0000268500 | Mengenkörper | no | 0 | AllplanAttributes - Material Architektur: Gipsfaserplatten 2-lagig (BSK); ash D_Detailverweis: <undefiniert>
 | H2 Ebene +2 | BS Bekleidung | yes | Zimmer- und Holzbauarbeiten | E00 | BS Bekleidung | 7.5 | 1205Kop0000268539 | Mengenkörper | no | 0 | AllplanAttributes - Material Architektur: Gipsfaserplatten 2-lagig (BSK); ash D_Detailverweis: <undefiniert>
 | H2 Ebene +2 | STB | yes | Betonarbeiten |  | STB | 7.5 | 1205Unz0000241900 | Unterzug | no | 0 | AllplanAttributes - Sicherheitsklasse: -; ash D_Detailverweis: <undefiniert>; Pset_BeamCommon - FireRating: 0
 | H2 Ebene +2 | H | yes | Zimmer- und Holzbauarbeiten |  | H | 7.5 | 1205Unz0000028422 | Unterzug | no | 0.9 | AllplanAttributes - Material Statik: BSH GL24c; Sicherheitsklasse: -; ash D_Detailverweis: <undefiniert>; Schallschutzklasse: 32; Sonnenschutztyp: Movable; g-Wert: 0,51; Pset_BeamCommon - FireRating: 0
 | H2 Ebene +2 | H | yes | Zimmer- und Holzbauarbeiten |  | H | 7.5 | 1205Unz0000026667 | Unterzug | no | 0.9 | AllplanAttributes - Material Statik: FSH Baubuche GL75; Sicherheitsklasse: -; ash D_Detailverweis: <undefiniert>; Schallschutzklasse: -; Sonnenschutztyp: Movable; g-Wert: 0,51; Pset_BeamCommon - FireRating: 0
 | H2 Ebene +2 | H | no | Zimmer- und Holzbauarbeiten |  | H | 7.5 | 1205Unz0000268307 | Unterzug | no | 0 | AllplanAttributes - Material Statik: NHC24; ash D_Detailverweis: <undefiniert>
 | H2 Ebene +2 | H | no | Zimmer- und Holzbauarbeiten |  | H | 7.5 | 1205Unz0000268360 | Unterzug | no | 0 | AllplanAttributes - Material Statik: NHC24; ash D_Detailverweis: <undefiniert>
 | H2 Ebene +2 | H | no | Zimmer- und Holzbauarbeiten |  | H | 7.5 | 1205Unz0000268399 | Unterzug | no | 0 | AllplanAttributes - Material Statik: NHC24; ash D_Detailverweis: <undefiniert>
 | H2 Ebene +2 | H | no | Zimmer- und Holzbauarbeiten |  | H | 7.5 | 1205Unz0000268438 | Unterzug | no | 0 | AllplanAttributes - Material Statik: NHC24; ash D_Detailverweis: <undefiniert>
 | H2 Ebene +2 | H | no | Zimmer- und Holzbauarbeiten |  | H | 7.5 | 1205Unz0000268477 | Unterzug | no | 0 | AllplanAttributes - Material Statik: NHC24; ash D_Detailverweis: <undefiniert>
 | H2 Ebene +2 | H | no | Zimmer- und Holzbauarbeiten |  | H | 7.5 | 1205Unz0000268516 | Unterzug | no | 0 | AllplanAttributes - Material Statik: NHC24; ash D_Detailverweis: <undefiniert>
 | H2 Ebene +2 | H | no | Zimmer- und Holzbauarbeiten |  | H | 7.5 | 1205Unz0000268555 | Unterzug | no | 0 | AllplanAttributes - Material Statik: NHC24; ash D_Detailverweis: <undefiniert>
 | H2 Ebene +2 | H | yes | Zimmer- und Holzbauarbeiten |  | H | 7.5 | 1205Unz0000027178 | Unterzug | no | 0.9 | AllplanAttributes - Material Statik: BSH GL24c; Sicherheitsklasse: -; ash D_Detailverweis: <undefiniert>; Schallschutzklasse: 32; Sonnenschutztyp: Movable; g-Wert: 0,51; Pset_BeamCommon - FireRating: 0
 | H2 Ebene +2 | H | yes | Zimmer- und Holzbauarbeiten |  | H | 7.5 | 1205Unz0000027188 | Unterzug | no | 0.9 | AllplanAttributes - Material Statik: BSH GL24c; Sicherheitsklasse: -; ash D_Detailverweis: <undefiniert>; Schallschutzklasse: 32; Sonnenschutztyp: Movable; g-Wert: 0,51; Pset_BeamCommon - FireRating: 0
 | H2 Ebene +2 | H | yes | Zimmer- und Holzbauarbeiten |  | H | 7.5 | 1205Unz0000028363 | Unterzug | no | 0.9 | AllplanAttributes - Material Statik: BSH GL24c; Sicherheitsklasse: -; ash D_Detailverweis: <undefiniert>; Schallschutzklasse: 32; Sonnenschutztyp: Movable; g-Wert: 0,51; Pset_BeamCommon - FireRating: 0
 | H2 Ebene +2 | H | yes | Zimmer- und Holzbauarbeiten |  | H | 7.5 | 1205Unz0000026630 | Unterzug | no | 0.9 | AllplanAttributes - Material Statik: FSH Baubuche GL75; Sicherheitsklasse: -; ash D_Detailverweis: <undefiniert>; Schallschutzklasse: -; Sonnenschutztyp: Movable; g-Wert: 0,51; Pset_BeamCommon - FireRating: 0
 | H2 Ebene +2 | H | yes | Zimmer- und Holzbauarbeiten |  | H | 7.5 | 1205Unz0000028384 | Unterzug | no | 0.9 | AllplanAttributes - Material Statik: BSH GL24c; Sicherheitsklasse: -; ash D_Detailverweis: <undefiniert>; Schallschutzklasse: 35; Sonnenschutztyp: Movable; g-Wert: 0,51; Pset_BeamCommon - FireRating: 0
 | H2 Ebene +2 | H | yes | Zimmer- und Holzbauarbeiten |  | H | 7.5 | 1205Unz0000028404 | Unterzug | no | 0.9 | AllplanAttributes - Material Statik: BSH GL24c; Sicherheitsklasse: -; ash D_Detailverweis: <undefiniert>; Schallschutzklasse: 32; Sonnenschutztyp: Movable; g-Wert: 0,51; Pset_BeamCommon - FireRating: 0
 | H2 Ebene +2 | BS Bekleidung | yes | Zimmer- und Holzbauarbeiten | E02 | BS Bekleidung | 7.5 | 1213Kop0813021677 | Stahlprofilträger | no | 0 | AllplanAttributes - Material Architektur: Gipsfaserplatten 2-lagig (BSK)
 | H2 Ebene +2 | BS Bekleidung | yes | Zimmer- und Holzbauarbeiten | E02 | BS Bekleidung | 7.5 | 1213Kop0813021618 | Mengenkörper | no | 0 | AllplanAttributes - Material Architektur: Gipsfaserplatten 2-lagig (BSK)
 | H2 Ebene +2 | BS Bekleidung | yes | Zimmer- und Holzbauarbeiten | E02 | BS Bekleidung | 7.5 | 1213Kop0813021609 | Mengenkörper | no | 0 | AllplanAttributes - Material Architektur: Gipsfaserplatten 2-lagig (BSK)
 | H2 Ebene +2 | BS Bekleidung | yes | Zimmer- und Holzbauarbeiten | E02 | BS Bekleidung | 7.5 | 1213Kop0813223091 | Mengenkörper | no | 0 | AllplanAttributes - Material Architektur: Gipsfaserplatten 2-lagig (BSK)
 | H2 Ebene +2 | BS Bekleidung | yes | Zimmer- und Holzbauarbeiten | E02 | BS Bekleidung | 7.5 | 1213Kop0813021624 | Mengenkörper | no | 0 | AllplanAttributes - Material Architektur: Gipsfaserplatten 2-lagig (BSK)
 | H2 Ebene +2 | BS Bekleidung | yes | Zimmer- und Holzbauarbeiten | E02 | BS Bekleidung | 7.5 | 1213Kop0813021630 | Mengenkörper | no | 0 | AllplanAttributes - Material Architektur: Gipsfaserplatten 2-lagig (BSK)
 | H2 Ebene +2 | BS Bekleidung | yes | Zimmer- und Holzbauarbeiten | E02 | BS Bekleidung | 7.5 | 1213Kop0813021627 | Mengenkörper | no | 0 | AllplanAttributes - Material Architektur: Gipsfaserplatten 2-lagig (BSK)
 | H2 Ebene +2 | BS Bekleidung | yes | Zimmer- und Holzbauarbeiten | E02 | BS Bekleidung | 7.5 | 1213Kop0813021659 | Mengenkörper | no | 0 | AllplanAttributes - Material Architektur: Gipsfaserplatten 2-lagig (BSK)
 | H2 Ebene +2 | BS Bekleidung | yes | Zimmer- und Holzbauarbeiten | E02 | BS Bekleidung | 7.5 | 1213Kop0813021563 | Mengenkörper | no | 0 | AllplanAttributes - Material Architektur: Gipsfaserplatten 2-lagig (BSK)
 | H2 Ebene +2 | BS Bekleidung | yes | Zimmer- und Holzbauarbeiten | E02 | BS Bekleidung | 7.5 | 1213Kop0813021642 | Mengenkörper | no | 0 | AllplanAttributes - Material Architektur: Gipsfaserplatten 2-lagig (BSK)
 | H2 Ebene +2 | BS Bekleidung | yes | Zimmer- und Holzbauarbeiten | E02 | BS Bekleidung | 7.5 | 1213Kop0813021580 | Mengenkörper | no | 0 | AllplanAttributes - Material Architektur: Gipsfaserplatten 2-lagig (BSK)
 | H2 Ebene +2 | BS Bekleidung | yes | Zimmer- und Holzbauarbeiten | E02 | BS Bekleidung | 7.5 | 1213Kop0813021546 | Mengenkörper | no | 0 | AllplanAttributes - Material Architektur: Gipsfaserplatten 2-lagig (BSK)
 | H2 Ebene +2 | BS Bekleidung | yes | Zimmer- und Holzbauarbeiten | E02 | BS Bekleidung | 7.5 | 1213Kop0813021505 | Mengenkörper | no | 0 | AllplanAttributes - Material Architektur: Gipsfaserplatten 2-lagig (BSK)
 | H2 Ebene +2 | BS Bekleidung | yes | Zimmer- und Holzbauarbeiten | E02 | BS Bekleidung | 7.5 | 1213Kop0813021606 | Mengenkörper | no | 0 | AllplanAttributes - Material Architektur: Gipsfaserplatten 2-lagig (BSK)
 | H2 Ebene +2 | BS Bekleidung | yes | Zimmer- und Holzbauarbeiten | E02 | BS Bekleidung | 7.5 | 1213Kop0813457049 | Mengenkörper | no | 0 | AllplanAttributes - Material Architektur: Gipsfaserplatten 2-lagig (BSK)
 | H2 Ebene +2 | BS Bekleidung | yes | Zimmer- und Holzbauarbeiten | E02 | BS Bekleidung | 7.5 | 1213Kop0813021615 | Mengenkörper | no | 0 | AllplanAttributes - Material Architektur: Gipsfaserplatten 2-lagig (BSK)
 | H2 Ebene +2 | BS Bekleidung | yes | Zimmer- und Holzbauarbeiten | E02 | BS Bekleidung | 7.5 | 1213Kop0813021621 | Mengenkörper | no | 0 | AllplanAttributes - Material Architektur: Gipsfaserplatten 2-lagig (BSK)
 | H2 Ebene +2 | BS Bekleidung | yes | Zimmer- und Holzbauarbeiten | E02 | BS Bekleidung | 7.5 | 1213Kop0813021603 | Mengenkörper | no | 0 | AllplanAttributes - Material Architektur: Gipsfaserplatten 2-lagig (BSK)
 | H2 Ebene +2 | BS Bekleidung | yes | Zimmer- und Holzbauarbeiten | E02 | BS Bekleidung | 7.5 | 1213Kop0813021531 | Mengenkörper | no | 0 | AllplanAttributes - Material Architektur: Gipsfaserplatten 2-lagig (BSK)
 | H2 Ebene +2 | BS Bekleidung | yes | Zimmer- und Holzbauarbeiten | E02 | BS Bekleidung | 7.5 | 1213Kop0813021543 | Mengenkörper | no | 0 | AllplanAttributes - Material Architektur: Gipsfaserplatten 2-lagig (BSK)
 | H2 Ebene +2 | BS Bekleidung | yes | Zimmer- und Holzbauarbeiten | E02 | BS Bekleidung | 7.5 | 1213Kop0813021633 | Mengenkörper | no | 0 | AllplanAttributes - Material Architektur: Gipsfaserplatten 2-lagig (BSK)
 | H2 Ebene +2 | BS Bekleidung | yes | Zimmer- und Holzbauarbeiten | E02 | BS Bekleidung | 7.5 | 1213Kop0813021540 | Mengenkörper | no | 0 | AllplanAttributes - Material Architektur: Gipsfaserplatten 2-lagig (BSK)
 | H2 Ebene +2 | BS Bekleidung | yes | Zimmer- und Holzbauarbeiten | E02 | BS Bekleidung | 7.5 | 1213Kop0813021528 | Mengenkörper | no | 0 | AllplanAttributes - Material Architektur: Gipsfaserplatten 2-lagig (BSK)
 | H2 Ebene +2 | BS Bekleidung | yes | Zimmer- und Holzbauarbeiten | E02 | BS Bekleidung | 7.5 | 1213Kop0813021701 | Mengenkörper | no | 0 | AllplanAttributes - Material Architektur: Gipsfaserplatten 2-lagig (BSK)
 | H2 Ebene +2 | BS Bekleidung | yes | Zimmer- und Holzbauarbeiten | E02 | BS Bekleidung | 7.5 | 1213Kop0813505945 | Mengenkörper | no | 0 | AllplanAttributes - Material Architektur: Gipsfaserplatten 2-lagig (BSK)
 | H2 Ebene +2 | H | no | Zimmer- und Holzbauarbeiten | E02 | H | 7.5 | 1213Unz0812970224 | Unterzug | no | 0 | AllplanAttributes - Material Statik: FSH Baubuche GL75
 | H2 Ebene +2 | H | no | Zimmer- und Holzbauarbeiten | E02 | H | 7.5 | 1213Unz0812970222 | Unterzug | no | 0 | AllplanAttributes - Material Statik: FSH Baubuche GL75
HEA140 | H2 Ebene +2 | HEA140 | yes | Stahlbauarbeiten | E02 | HEA140 | 7.5 | 1213Unz0812970987 | Stahlprofilträger | yes | AllplanAttributes - Bezeichnung: HEA140; Pset_BeamCommon - FireRating: REI 90-A1
HEB260 | H2 Ebene +2 | HEB260 | yes | Stahlbauarbeiten | E02 | HEB260 | 7.5 | 1213Unz0812970977 | Stahlprofilträger | yes | AllplanAttributes - Bezeichnung: HEB260; Pset_BeamCommon - FireRating: REI 90-A1
HEA240 | H2 Ebene +2 | HEA240 | yes | Stahlbauarbeiten | E02 | HEA240 | 7.5 | 1213Unz0812970979 | Stahlprofilträger | yes | AllplanAttributes - Bezeichnung: HEA240; Pset_BeamCommon - FireRating: REI 90-A1
HEB260 | H2 Ebene +2 | HEB260 | yes | Stahlbauarbeiten | E02 | HEB260 | 7.5 | 1213Unz0812970981 | Stahlprofilträger | yes | AllplanAttributes - Bezeichnung: HEB260; Pset_BeamCommon - FireRating: REI 90-A1
HEA240 | H2 Ebene +2 | HEA240 | yes | Stahlbauarbeiten | E02 | HEA240 | 7.5 | 1213Unz0812970999 | Stahlprofilträger | yes | AllplanAttributes - Bezeichnung: HEA240; Pset_BeamCommon - FireRating: REI 90-A1
HEA240 | H2 Ebene +2 | HEA240 | yes | Stahlbauarbeiten | E02 | HEA240 | 7.5 | 1213Unz0812970983 | Stahlprofilträger | yes | AllplanAttributes - Bezeichnung: HEA240; Pset_BeamCommon - FireRating: REI 90-A1
HEA240 | H2 Ebene +2 | HEA240 | yes | Stahlbauarbeiten | E02 | HEA240 | 7.5 | 1213Unz0812970991 | Stahlprofilträger | yes | AllplanAttributes - Bezeichnung: HEA240; Pset_BeamCommon - FireRating: REI 90-A1
HEA140 | H2 Ebene +2 | HEA140 | yes | Stahlbauarbeiten | E02 | HEA140 | 7.5 | 1213Unz0812970995 | Stahlprofilträger | yes | AllplanAttributes - Bezeichnung: HEA140; Pset_BeamCommon - FireRating: REI 90-A1
HEA240 | H2 Ebene +2 | HEA240 | yes | Stahlbauarbeiten | E02 | HEA240 | 7.5 | 1213Unz0812970997 | Stahlprofilträger | yes | AllplanAttributes - Bezeichnung: HEA240; Pset_BeamCommon - FireRating: REI 90-A1
HEA240 | H2 Ebene +2 | HEA240 | yes | Stahlbauarbeiten | E02 | HEA240 | 7.5 | 1213Unz0812970989 | Stahlprofilträger | yes | AllplanAttributes - Bezeichnung: HEA240; Pset_BeamCommon - FireRating: REI 90-A1
HEA140 | H2 Ebene +2 | HEA140 | yes | Stahlbauarbeiten | E02 | HEA140 | 7.5 | 1213Unz0812970985 | Stahlprofilträger | yes | AllplanAttributes - Bezeichnung: HEA140; Pset_BeamCommon - FireRating: REI 90-A1
HEB140 | H2 Ebene +2 | HEB140 | yes | Stahlbauarbeiten | E02 | HEB140 | 7.5 | 1213Unz0812970993 | Stahlprofilträger | yes | AllplanAttributes - Bezeichnung: HEB140; Pset_BeamCommon - FireRating: REI 90-A1
 | H2 Ebene +2 | H | yes | Zimmer- und Holzbauarbeiten | E02 | H | 7.5 | 1213Unz0812970232 | Unterzug | no | 0 | AllplanAttributes - Material Statik: FSH Baubuche GL75
 | H2 Ebene +2 | H | yes | Zimmer- und Holzbauarbeiten | E02 | H | 7.5 | 1213Unz0812970238 | Unterzug | no | 0 | AllplanAttributes - Material Statik: NH C24
 | H2 Ebene +2 | H | yes | Zimmer- und Holzbauarbeiten | E02 | H | 7.5 | 1213Unz0812970234 | Unterzug | no | 0 | AllplanAttributes - Material Statik: NH C24
 | H2 Ebene +2 | H | yes | Zimmer- und Holzbauarbeiten | E02 | H | 7.5 | 1213Unz0812970249 | Unterzug | no | 0 | AllplanAttributes - Material Statik: FSH Baubuche GL75
 | H2 Ebene +2 | STB | no | Betonarbeiten | E02 | STB | 7.5 | 1213Unz0812970214 | Überzug | no | 0 | AllplanAttributes - Material Statik: Stahlbeton
 | H2 Ebene +2 | H | yes | Zimmer- und Holzbauarbeiten | E02 | H | 7.5 | 1213Unz0812970158 | Unterzug | no | 0 | AllplanAttributes - Material Statik: NH C24
 | H2 Ebene +2 | H | yes | Zimmer- und Holzbauarbeiten | E02 | H | 7.5 | 1213Unz0812970247 | Unterzug | no | 0 | AllplanAttributes - Material Statik: NH C24
 | H2 Ebene +2 | STB | no | Betonarbeiten | E02 | STB | 7.5 | 1213Unz0812970242 | Überzug | no | 0 | AllplanAttributes - Material Statik: STB
 | H2 Ebene +2 | STB | no | Betonarbeiten | E02 | STB | 7.5 | 1213Unz0812970240 | Überzug | no | 0 | AllplanAttributes - Material Statik: STB
 | H2 Ebene +2 | STB | no | Betonarbeiten | E02 | STB | 7.5 | 1213Unz0812970230 | Überzug | no | 0 | AllplanAttributes - Material Statik: NH C24
 | H2 Ebene +2 | STB | no | Betonarbeiten | E02 | STB | 7.5 | 1213Unz0812970228 | Überzug | no | 0 | AllplanAttributes - Material Statik: STB
 | H2 Ebene +2 | H | no | Zimmer- und Holzbauarbeiten | E02 | H | 7.5 | 1213Unz0812969893 | Unterzug | no | 0 | AllplanAttributes - Material Statik: FSH Baubuche GL75
 | H2 Ebene +2 | H | no | Zimmer- und Holzbauarbeiten | E02 | H | 7.5 | 1213Unz0812970043 | Unterzug | no | 0 | AllplanAttributes - Material Statik: FSH Baubuche GL75
 | H2 Ebene +2 | H | no | Zimmer- und Holzbauarbeiten | E02 | H | 7.5 | 1213Unz0812970122 | Unterzug | no | 0 | AllplanAttributes - Material Statik: FSH Baubuche GL75
 | H2 Ebene +2 | H | no | Zimmer- und Holzbauarbeiten | E02 | H | 7.5 | 1213Unz0812970063 | Unterzug | no | 0 | AllplanAttributes - Material Statik: FSH Baubuche GL75
 | H2 Ebene +2 | H | no | Zimmer- und Holzbauarbeiten | E02 | H | 7.5 | 1213Unz0813505973 | Unterzug | no | 0 | AllplanAttributes - Material Statik: FSH Baubuche GL75; Positionsnummer_Text: U100
 | H2 Ebene +2 | STB | no | Betonarbeiten | E02 | STB | 7.5 | 1213Unz0812970220 | Überzug | no | 0 | AllplanAttributes - Material Statik: STB
 | H2 Ebene +2 | STB | no | Betonarbeiten | E02 | STB | 7.5 | 1213Unz0812970216 | Überzug | no | 0 | AllplanAttributes - Material Statik: NH C24
 | H2 Ebene +2 | STB | no | Betonarbeiten | E02 | STB | 7.5 | 1213Unz0812970218 | Überzug | no | 0 | AllplanAttributes - Material Statik: NH C24
 | H2 Ebene +2 | STB | no | Betonarbeiten | E02 | STB | 7.5 | 1213Unz0812970226 | Überzug | no | 0 | AllplanAttributes - Material Statik: STB
 | H2 Ebene +2 | STB | yes | Betonarbeiten | E02 | STB | 7.5 | 1213Unz0813061759 | Unterzug | no | 0 | AllplanAttributes - Sicherheitsklasse: -; Pset_BeamCommon - FireRating: 0
FS-Vorhang | H2 Ebene +2 |  | no | Zusatzgewerk Kunde |  |  | 0 | 1213Unz0813500130 | Brandschutzvorhang | no | 0 | AllplanAttributes - Text1: S200 C2; Bezeichnung: FS-Vorhang; Rauchschutz: yes; Selbstschließend: yes; Sicherheitsklasse: -; ash T_Tür-Nr.: FS-Vorhang; ash T_Raum zugehörigkeit: BS; Pset_BeamCommon - FireRating: EW 60
 | H2 Ebene +2 | STB | yes | Betonarbeiten | E02 | STB | 7.5 | 1213Unz0813061847 | Unterzug | no | 0 | AllplanAttributes - Sicherheitsklasse: -; Pset_BeamCommon - FireRating: 0
 | H2 Ebene +2 | STB | yes | Betonarbeiten | E02 | STB | 7.5 | 1213Unz0813061804 | Unterzug | no | 0 | AllplanAttributes - Sicherheitsklasse: -; Pset_BeamCommon - FireRating: 0
FS-Vorhang | H2 Ebene +2 |  | no | Zusatzgewerk Kunde |  |  | 0 | 1213Unz0813500410 | Brandschutzvorhang | no | 0 | AllplanAttributes - Text1: S200 C2; Bezeichnung: FS-Vorhang; Rauchschutz: yes; Selbstschließend: yes; Sicherheitsklasse: -; ash T_Tür-Nr.: FS-Vorhang; ash T_Raum zugehörigkeit: BS; Pset_BeamCommon - FireRating: EI2 60
 | H2 Ebene +2 | STB | no | Betonarbeiten | E02 | STB | 7.5 | 1213Unz0812970236 | Überzug | no | 0 | AllplanAttributes - Material Statik: Stahlbeton
HEA160 | H2 Ebene +2 | SB-TRAEGER | yes | Stahlbauarbeiten |  | SB-TRAEGER |  | 1214Unz0000002878 | Stahlprofilträger | yes | AllplanAttributes - Bezeichnung: HEA160; Pset_BeamCommon - FireRating: REI 90-A1
HEA160 | H2 Ebene +2 | SB-TRAEGER | yes | Stahlbauarbeiten |  | SB-TRAEGER |  | 1214Unz0000002815 | Stahlprofilträger | yes | AllplanAttributes - Bezeichnung: HEA160; Pset_BeamCommon - FireRating: REI 90-A1
HEA160 | H2 Ebene +2 | SB-TRAEGER | yes | Stahlbauarbeiten |  | SB-TRAEGER |  | 1214Unz0000002821 | Stahlprofilträger | yes | AllplanAttributes - Bezeichnung: HEA160; Pset_BeamCommon - FireRating: REI 90-A1
HEA160 | H2 Ebene +2 | SB-TRAEGER | yes | Stahlbauarbeiten |  | SB-TRAEGER |  | 1214Unz0000002791 | Stahlprofilträger | yes | AllplanAttributes - Bezeichnung: HEA160; Pset_BeamCommon - FireRating: REI 90-A1
HEA160 | H2 Ebene +2 | SB-TRAEGER | yes | Stahlbauarbeiten |  | SB-TRAEGER |  | 1214Unz0000002827 | Stahlprofilträger | yes | AllplanAttributes - Bezeichnung: HEA160; Pset_BeamCommon - FireRating: REI 90-A1
HEA160 | H2 Ebene +2 | SB-TRAEGER | yes | Stahlbauarbeiten |  | SB-TRAEGER |  | 1214Unz0000002866 | Stahlprofilträger | yes | AllplanAttributes - Bezeichnung: HEA160; Pset_BeamCommon - FireRating: REI 90-A1
HEA160 | H2 Ebene +2 | SB-TRAEGER | yes | Stahlbauarbeiten |  | SB-TRAEGER |  | 1214Unz0000002872 | Stahlprofilträger | yes | AllplanAttributes - Bezeichnung: HEA160; Pset_BeamCommon - FireRating: REI 90-A1
HEA160 | H2 Ebene +2 | SB-TRAEGER | yes | Stahlbauarbeiten |  | SB-TRAEGER |  | 1214Unz0000002837 | Stahlprofilträger | yes | AllplanAttributes - Bezeichnung: HEA160; Pset_BeamCommon - FireRating: REI 90-A1
 | H2 Ebene +1 | BS Bekleidung | yes | Zimmer- und Holzbauarbeiten | E00 | BS Bekleidung | 3.75 | 1155Kop0000174618 | Mengenkörper | no | 0 | AllplanAttributes - Material Architektur: Gipsfaserplatten 2-lagig (BSK)
 | H2 Ebene +1 | BS Bekleidung | yes | Zimmer- und Holzbauarbeiten | E00 | BS Bekleidung | 3.75 | 1155Kop0813753984 | Mengenkörper | no | 0 | AllplanAttributes - Material Architektur: Gipsfaserplatten 2-lagig (BSK)
 | H2 Ebene +1 | BS Bekleidung | yes | Zimmer- und Holzbauarbeiten | E00 | BS Bekleidung | 3.75 | 1155Kop0813764687 | Mengenkörper | no | 0 | AllplanAttributes - Material Architektur: Gipsfaserplatten 2-lagig (BSK)
 | H2 Ebene +1 | BS Bekleidung | yes | Zimmer- und Holzbauarbeiten | E00 | BS Bekleidung | 3.75 | 1155Kop0813765332 | Mengenkörper | no | 0 | AllplanAttributes - Material Architektur: Gipsfaserplatten 2-lagig (BSK)
 | H2 Ebene +1 | BS Bekleidung | yes | Zimmer- und Holzbauarbeiten | E00 | BS Bekleidung | 3.75 | 1155Kop0813765385 | Mengenkörper | no | 0 | AllplanAttributes - Material Architektur: Gipsfaserplatten 2-lagig (BSK)
 | H2 Ebene +1 | BS Bekleidung | yes | Zimmer- und Holzbauarbeiten | E00 | BS Bekleidung | 3.75 | 1155Kop0813765426 | Mengenkörper | no | 0 | AllplanAttributes - Material Architektur: Gipsfaserplatten 2-lagig (BSK)
 | H2 Ebene +1 | BS Bekleidung | yes | Zimmer- und Holzbauarbeiten | E00 | BS Bekleidung | 3.75 | 1155Kop0813765481 | Mengenkörper | no | 0 | AllplanAttributes - Material Architektur: Gipsfaserplatten 2-lagig (BSK)
 | H2 Ebene +1 | BS Bekleidung | yes | Zimmer- und Holzbauarbeiten | E00 | BS Bekleidung | 3.75 | 1155Kop0813765522 | Mengenkörper | no | 0 | AllplanAttributes - Material Architektur: Gipsfaserplatten 2-lagig (BSK)
 | H2 Ebene +1 | BS Bekleidung | yes | Zimmer- und Holzbauarbeiten | E00 | BS Bekleidung | 3.75 | 1155Kop0813765601 | Mengenkörper | no | 0 | AllplanAttributes - Material Architektur: Gipsfaserplatten 2-lagig (BSK)
 | H2 Ebene +1 | BS Bekleidung | yes | Zimmer- und Holzbauarbeiten | E00 | BS Bekleidung | 3.75 | 1155Kop0813765642 | Mengenkörper | no | 0 | AllplanAttributes - Material Architektur: Gipsfaserplatten 2-lagig (BSK)
 | H2 Ebene +1 | BS Bekleidung | yes | Zimmer- und Holzbauarbeiten | E00 | BS Bekleidung | 3.75 | 1155Kop0813765704 | Mengenkörper | no | 0 | AllplanAttributes - Material Architektur: Gipsfaserplatten 2-lagig (BSK)
 | H2 Ebene +1 | BS Bekleidung | yes | Zimmer- und Holzbauarbeiten | E00 | BS Bekleidung | 3.75 | 1155Kop0813765750 | Mengenkörper | no | 0 | AllplanAttributes - Material Architektur: Gipsfaserplatten 2-lagig (BSK)
 | H2 Ebene +1 | BS Bekleidung | yes | Zimmer- und Holzbauarbeiten | E00 | BS Bekleidung | 3.75 | 1155Kop0813765900 | Mengenkörper | no | 0 | AllplanAttributes - Material Architektur: Gipsfaserplatten 2-lagig (BSK)
 | H2 Ebene +1 | BS Bekleidung | yes | Zimmer- und Holzbauarbeiten | E00 | BS Bekleidung | 3.75 | 1155Kop0813765933 | Mengenkörper | no | 0 | AllplanAttributes - Material Architektur: Gipsfaserplatten 2-lagig (BSK)
 | H2 Ebene +1 | BS Bekleidung | yes | Zimmer- und Holzbauarbeiten | E00 | BS Bekleidung | 3.75 | 1155Kop0813765970 | Mengenkörper | no | 0 | AllplanAttributes - Material Architektur: Gipsfaserplatten 2-lagig (BSK)
 | H2 Ebene +1 | BS Bekleidung | yes | Zimmer- und Holzbauarbeiten | E00 | BS Bekleidung | 3.75 | 1155Kop0813766009 | Mengenkörper | no | 0 | AllplanAttributes - Material Architektur: Gipsfaserplatten 2-lagig (BSK)
 | H2 Ebene +1 | H | yes | Zimmer- und Holzbauarbeiten |  | H | 3.75 | 1155Unz0000027188 | Unterzug | no | 0.9 | AllplanAttributes - Material Statik: BSH GL24c; Positionsnummer_Text: U23; Sicherheitsklasse: -; Schallschutzklasse: 32; Sonnenschutztyp: Movable; g-Wert: 0,51; Pset_BeamCommon - FireRating: 0
 | H2 Ebene +1 | H | yes | Zimmer- und Holzbauarbeiten |  | H | 3.75 | 1155Unz0000027178 | Unterzug | no | 0.9 | AllplanAttributes - Material Statik: BSH GL24c; Positionsnummer_Text: U23; Sicherheitsklasse: -; Schallschutzklasse: 32; Sonnenschutztyp: Movable; g-Wert: 0,51; Pset_BeamCommon - FireRating: 0
 | H2 Ebene +1 | ÜZ-H | yes | Zimmer- und Holzbauarbeiten |  | ÜZ-H | 3.75 | 1155Unz0813766011 | Unterzug | no | 0 | AllplanAttributes - Material Statik: NHC24; Positionsnummer_Text: U43
 | H2 Ebene +1 | H | no | Zimmer- und Holzbauarbeiten | E00 | H | 3.75 | 1155Unz0813754325 | Unterzug | no | 0 | AllplanAttributes - Positionsnummer_Text: U23; Sicherheitsklasse: -; Pset_BeamCommon - FireRating: 0
 | H2 Ebene +1 | H | yes | Zimmer- und Holzbauarbeiten |  | H | 3.75 | 1155Unz0000026667 | Unterzug | no | 0.9 | AllplanAttributes - Material Statik: FSH Baubuche GL75; Positionsnummer_Text: U23; Sicherheitsklasse: -; Schallschutzklasse: 32; Sonnenschutztyp: Movable; g-Wert: 0,51; Pset_BeamCommon - FireRating: 0
 | H2 Ebene +1 | H | yes | Zimmer- und Holzbauarbeiten |  | H | 3.75 | 1155Unz0813755544 | Unterzug | no | 0.9 | AllplanAttributes - Material Statik: FSH Baubuche GL75; Positionsnummer_Text: U23; Sicherheitsklasse: -; Schallschutzklasse: 32; Sonnenschutztyp: Movable; g-Wert: 0,51; Pset_BeamCommon - FireRating: 0
 | H2 Ebene +1 | ÜZ-H | yes | Zimmer- und Holzbauarbeiten |  | ÜZ-H | 3.75 | 1155Unz0813765645 | Unterzug | no | 0 | AllplanAttributes - Material Statik: NHC24; Positionsnummer_Text: U43
 | H2 Ebene +1 | ÜZ-H | yes | Zimmer- und Holzbauarbeiten |  | ÜZ-H | 3.75 | 1155Unz0813765972 | Unterzug | no | 0 | AllplanAttributes - Material Statik: NHC24; Positionsnummer_Text: U43
 | H2 Ebene +1 | ÜZ-H | yes | Zimmer- und Holzbauarbeiten |  | ÜZ-H | 3.75 | 1155Unz0813765931 | Unterzug | no | 0 | AllplanAttributes - Material Statik: NHC24; Positionsnummer_Text: U43
 | H2 Ebene +1 | ÜZ-H | yes | Zimmer- und Holzbauarbeiten |  | ÜZ-H | 3.75 | 1155Unz0813765879 | Unterzug | no | 0 | AllplanAttributes - Material Statik: NHC24; Positionsnummer_Text: U43
 | H2 Ebene +1 | ÜZ-H | yes | Zimmer- und Holzbauarbeiten |  | ÜZ-H | 3.75 | 1155Unz0813765721 | Unterzug | no | 0 | AllplanAttributes - Material Statik: NHC24; Positionsnummer_Text: U43
 | H2 Ebene +1 | ÜZ-H | yes | Zimmer- und Holzbauarbeiten |  | ÜZ-H | 3.75 | 1155Unz0813765767 | Unterzug | no | 0 | AllplanAttributes - Material Statik: NHC24; Positionsnummer_Text: U43
 | H2 Ebene +1 | ÜZ-H | yes | Zimmer- und Holzbauarbeiten |  | ÜZ-H | 3.75 | 1155Unz0813764704 | Unterzug | no | 0 | AllplanAttributes - Material Statik: NHC24; Positionsnummer_Text: U43
 | H2 Ebene +1 | ÜZ-H | yes | Zimmer- und Holzbauarbeiten |  | ÜZ-H | 3.75 | 1155Unz0813765349 | Unterzug | no | 0 | AllplanAttributes - Material Statik: NHC24; Positionsnummer_Text: U43
 | H2 Ebene +1 | ÜZ-H | yes | Zimmer- und Holzbauarbeiten |  | ÜZ-H | 3.75 | 1155Unz0813765402 | Unterzug | no | 0 | AllplanAttributes - Material Statik: NHC24; Positionsnummer_Text: U43
 | H2 Ebene +1 | ÜZ-H | yes | Zimmer- und Holzbauarbeiten |  | ÜZ-H | 3.75 | 1155Unz0813765443 | Unterzug | no | 0 | AllplanAttributes - Material Statik: NHC24; Positionsnummer_Text: U43
 | H2 Ebene +1 | ÜZ-H | yes | Zimmer- und Holzbauarbeiten |  | ÜZ-H | 3.75 | 1155Unz0813765498 | Unterzug | no | 0 | AllplanAttributes - Material Statik: NHC24; Positionsnummer_Text: U43
 | H2 Ebene +1 | ÜZ-H | yes | Zimmer- und Holzbauarbeiten |  | ÜZ-H | 3.75 | 1155Unz0813765539 | Unterzug | no | 0 | AllplanAttributes - Material Statik: NHC24; Positionsnummer_Text: U43
 | H2 Ebene +1 | ÜZ-H | yes | Zimmer- und Holzbauarbeiten |  | ÜZ-H | 3.75 | 1155Unz0813765604 | Unterzug | no | 0 | AllplanAttributes - Material Statik: NHC24; Positionsnummer_Text: U43
 | H2 Ebene +1 | STB | yes | Betonarbeiten |  | STB | 3.75 | 1155Unz0000173354 | Unterzug | no | 0 | AllplanAttributes - Positionsnummer_Text: U23; Sicherheitsklasse: -; Pset_BeamCommon - FireRating: 0
 | H2 Ebene +1 | BS Bekleidung | yes | Zimmer- und Holzbauarbeiten | E01 | BS Bekleidung | 3.75 | 1163Kop0813668617 | Stahlprofilträger | no | 0 | AllplanAttributes - Material Architektur: Gipsfaserplatten 2-lagig (BSK)
HEA140 | H2 Ebene +1 | HEA140 | yes | Stahlbauarbeiten | E01 | HEA140 | 3.75 | 1163Unz0812746839 | Stahlprofilträger | yes | AllplanAttributes - Positionsnummer_Text: U100; Bezeichnung: HEA140; Pset_BeamCommon - FireRating: REI 90-A1
HEA240 | H2 Ebene +1 | HEA240 | yes | Stahlbauarbeiten | E01 | HEA240 | 3.75 | 1163Unz0812833051 | Stahlprofilträger | yes | AllplanAttributes - Positionsnummer_Text: U27; Bezeichnung: HEA240; Pset_BeamCommon - FireRating: REI 90-A1
HEA240 | H2 Ebene +1 | HEA240 | yes | Stahlbauarbeiten | E01 | HEA240 | 3.75 | 1163Unz0812747276 | Stahlprofilträger | yes | AllplanAttributes - Positionsnummer_Text: U32; Bezeichnung: HEA240; Pset_BeamCommon - FireRating: REI 90-A1
HEA240 | H2 Ebene +1 | HEA240 | yes | Stahlbauarbeiten | E01 | HEA240 | 3.75 | 1163Unz0812747122 | Stahlprofilträger | yes | AllplanAttributes - Positionsnummer_Text: U34; Bezeichnung: HEA240; Pset_BeamCommon - FireRating: REI 90-A1
HEA240 | H2 Ebene +1 | HEA240 | yes | Stahlbauarbeiten | E01 | HEA240 | 3.75 | 1163Unz0812746965 | Stahlprofilträger | yes | AllplanAttributes - Positionsnummer_Text: U33; Bezeichnung: HEA240; Pset_BeamCommon - FireRating: REI 90-A1
HEA140 | H2 Ebene +1 | HEA140 | yes | Stahlbauarbeiten | E01 | HEA140 | 3.75 | 1163Unz0812747028 | Stahlprofilträger | yes | AllplanAttributes - Positionsnummer_Text: U26; Bezeichnung: HEA140; Pset_BeamCommon - FireRating: REI 90-A1
HEA140 | H2 Ebene +1 | HEA140 | yes | Stahlbauarbeiten |  | HEA140 | 3.75 | 1163Unz0812747058 | Stahlprofilträger | yes | AllplanAttributes - Positionsnummer_Text: U25; Bezeichnung: HEA140; Pset_BeamCommon - FireRating: REI 90-A1
HEA240 | H2 Ebene +1 | HEA240 | yes | Stahlbauarbeiten |  | HEA240 | 3.75 | 1163Unz0812746991 | Stahlprofilträger | yes | AllplanAttributes - Positionsnummer_Text: U28; Bezeichnung: HEA240; Pset_BeamCommon - FireRating: REI 90-A1
HEA240 | H2 Ebene +1 | HEA240 | yes | Stahlbauarbeiten |  | HEA240 | 3.75 | 1163Unz0812747129 | Stahlprofilträger | yes | AllplanAttributes - Positionsnummer_Text: U28; Bezeichnung: HEA240; Pset_BeamCommon - FireRating: REI 90-A1
HEA140 | H2 Ebene +1 | HEA140 | yes | Stahlbauarbeiten |  | HEA140 | 3.75 | 1163Unz0812747270 | Stahlprofilträger | yes | AllplanAttributes - Positionsnummer_Text: U26; Bezeichnung: HEA140; Pset_BeamCommon - FireRating: REI 90-A1
HEA240 | H2 Ebene +1 | HEA240 | yes | Stahlbauarbeiten |  | HEA240 | 3.75 | 1163Unz0812833047 | Stahlprofilträger | yes | AllplanAttributes - Positionsnummer_Text: U27; Bezeichnung: HEA240; Pset_BeamCommon - FireRating: REI 90-A1
HEA240 | H2 Ebene +1 | HEA240 | yes | Stahlbauarbeiten | E01 | HEA240 | 3.75 | 1163Unz0812746961 | Stahlprofilträger | yes | AllplanAttributes - Positionsnummer_Text: U32; Bezeichnung: HEA240; Pset_BeamCommon - FireRating: REI 90-A1
 | H2 Ebene +1 | BS Bekleidung | yes | Zimmer- und Holzbauarbeiten | E01 | BS Bekleidung | 3.75 | 1163Kop0813668605 | Mengenkörper | no | 0 | AllplanAttributes - Material Architektur: Gipsfaserplatten 2-lagig (BSK)
 | H2 Ebene +1 | BS Bekleidung | yes | Zimmer- und Holzbauarbeiten | E01 | BS Bekleidung | 3.75 | 1163Kop0813668569 | Mengenkörper | no | 0 | AllplanAttributes - Material Architektur: Gipsfaserplatten 2-lagig (BSK)
 | H2 Ebene +1 | BS Bekleidung | yes | Zimmer- und Holzbauarbeiten | E01 | BS Bekleidung | 3.75 | 1163Kop0813668587 | Mengenkörper | no | 0 | AllplanAttributes - Material Architektur: Gipsfaserplatten 2-lagig (BSK)
 | H2 Ebene +1 | BS Bekleidung | yes | Zimmer- und Holzbauarbeiten | E01 | BS Bekleidung | 3.75 | 1163Kop0813668566 | Mengenkörper | no | 0 | AllplanAttributes - Material Architektur: Gipsfaserplatten 2-lagig (BSK)
 | H2 Ebene +1 | BS Bekleidung | yes | Zimmer- und Holzbauarbeiten | E01 | BS Bekleidung | 3.75 | 1163Kop0813668572 | Mengenkörper | no | 0 | AllplanAttributes - Material Architektur: Gipsfaserplatten 2-lagig (BSK)
 | H2 Ebene +1 | BS Bekleidung | yes | Zimmer- und Holzbauarbeiten | E01 | BS Bekleidung | 3.75 | 1163Kop0813668584 | Mengenkörper | no | 0 | AllplanAttributes - Material Architektur: Gipsfaserplatten 2-lagig (BSK)
 | H2 Ebene +1 | BS Bekleidung | yes | Zimmer- und Holzbauarbeiten | E01 | BS Bekleidung | 3.75 | 1163Kop0813668590 | Mengenkörper | no | 0 | AllplanAttributes - Material Architektur: Gipsfaserplatten 2-lagig (BSK)
 | H2 Ebene +1 | BS Bekleidung | yes | Zimmer- und Holzbauarbeiten | E01 | BS Bekleidung | 3.75 | 1163Kop0813668554 | Mengenkörper | no | 0 | AllplanAttributes - Material Architektur: Gipsfaserplatten 2-lagig (BSK)
 | H2 Ebene +1 | BS Bekleidung | yes | Zimmer- und Holzbauarbeiten | E01 | BS Bekleidung | 3.75 | 1163Kop0813668551 | Mengenkörper | no | 0 | AllplanAttributes - Material Architektur: Gipsfaserplatten 2-lagig (BSK)
 | H2 Ebene +1 | BS Bekleidung | yes | Zimmer- und Holzbauarbeiten | E01 | BS Bekleidung | 3.75 | 1163Kop0813668548 | Mengenkörper | no | 0 | AllplanAttributes - Material Architektur: Gipsfaserplatten 2-lagig (BSK)
 | H2 Ebene +1 | BS Bekleidung | yes | Zimmer- und Holzbauarbeiten | E01 | BS Bekleidung | 3.75 | 1163Kop0813668602 | Mengenkörper | no | 0 | AllplanAttributes - Material Architektur: Gipsfaserplatten 2-lagig (BSK)
 | H2 Ebene +1 | BS Bekleidung | yes | Zimmer- und Holzbauarbeiten | E01 | BS Bekleidung | 3.75 | 1163Kop0813668521 | Mengenkörper | no | 0 | AllplanAttributes - Material Architektur: Gipsfaserplatten 2-lagig (BSK)
 | H2 Ebene +1 | BS Bekleidung | yes | Zimmer- und Holzbauarbeiten | E01 | BS Bekleidung | 3.75 | 1163Kop0814354759 | Mengenkörper | no | 0 | AllplanAttributes - Material Architektur: Gipsfaserplatten 2-lagig (BSK)
 | H2 Ebene +1 | BS Bekleidung | yes | Zimmer- und Holzbauarbeiten | E01 | BS Bekleidung | 3.75 | 1163Kop0813668575 | Mengenkörper | no | 0 | AllplanAttributes - Material Architektur: Gipsfaserplatten 2-lagig (BSK)
 | H2 Ebene +1 | BS Bekleidung | yes | Zimmer- und Holzbauarbeiten | E01 | BS Bekleidung | 3.75 | 1163Kop0813668581 | Mengenkörper | no | 0 | AllplanAttributes - Material Architektur: Gipsfaserplatten 2-lagig (BSK)
 | H2 Ebene +1 | BS Bekleidung | yes | Zimmer- und Holzbauarbeiten | E01 | BS Bekleidung | 3.75 | 1163Kop0814370807 | Mengenkörper | no | 0 | AllplanAttributes - Material Architektur: Gipsfaserplatten 2-lagig (BSK)
 | H2 Ebene +1 | BS Bekleidung | yes | Zimmer- und Holzbauarbeiten | E01 | BS Bekleidung | 3.75 | 1163Kop0813668563 | Mengenkörper | no | 0 | AllplanAttributes - Material Architektur: Gipsfaserplatten 2-lagig (BSK)
 | H2 Ebene +1 | BS Bekleidung | yes | Zimmer- und Holzbauarbeiten | E01 | BS Bekleidung | 3.75 | 1163Kop0813668545 | Mengenkörper | no | 0 | AllplanAttributes - Material Architektur: Gipsfaserplatten 2-lagig (BSK)
 | H2 Ebene +1 | BS Bekleidung | yes | Zimmer- und Holzbauarbeiten | E01 | BS Bekleidung | 3.75 | 1163Kop0813668533 | Mengenkörper | no | 0 | AllplanAttributes - Material Architektur: Gipsfaserplatten 2-lagig (BSK)
 | H2 Ebene +1 | BS Bekleidung | yes | Zimmer- und Holzbauarbeiten | E01 | BS Bekleidung | 3.75 | 1163Kop0813668614 | Mengenkörper | no | 0 | AllplanAttributes - Material Architektur: Gipsfaserplatten 2-lagig (BSK)
 | H2 Ebene +1 | BS Bekleidung | yes | Zimmer- und Holzbauarbeiten | E01 | BS Bekleidung | 3.75 | 1163Kop0813668530 | Mengenkörper | no | 0 | AllplanAttributes - Material Architektur: Gipsfaserplatten 2-lagig (BSK)
 | H2 Ebene +1 | BS Bekleidung | yes | Zimmer- und Holzbauarbeiten | E01 | BS Bekleidung | 3.75 | 1163Kop0813668542 | Mengenkörper | no | 0 | AllplanAttributes - Material Architektur: Gipsfaserplatten 2-lagig (BSK)
 | H2 Ebene +1 | BS Bekleidung | yes | Zimmer- und Holzbauarbeiten | E01 | BS Bekleidung | 3.75 | 1163Kop0813668593 | Mengenkörper | no | 0 | AllplanAttributes - Material Architektur: Gipsfaserplatten 2-lagig (BSK)
 | H2 Ebene +1 | BS Bekleidung | yes | Zimmer- und Holzbauarbeiten | E01 | BS Bekleidung | 3.75 | 1163Kop0813668578 | Mengenkörper | no | 0 | AllplanAttributes - Material Architektur: Gipsfaserplatten 2-lagig (BSK); ash D_Detailverweis: D1; ash D_Plannummer: 1680
 | H2 Ebene +1 | H | yes | Zimmer- und Holzbauarbeiten |  | H | 3.75 | 1163Unz0812536506 | Unterzug | no | 0 | AllplanAttributes - Material Statik: FSH Baubuche GL75; Positionsnummer_Text: U20
 | H2 Ebene +1 | H | yes | Zimmer- und Holzbauarbeiten |  | H | 3.75 | 1163Unz0812536514 | Unterzug | no | 0 | AllplanAttributes - Material Statik: FSH Baubuche GL75; Positionsnummer_Text: U20
 | H2 Ebene +1 | STB | no | Betonarbeiten | E01 | STB | 3.75 | 1163Unz0812903228 | Überzug | no | 0 | AllplanAttributes - Material Statik: STB; Positionsnummer_Text: U100
 | H2 Ebene +1 | STB | no | Betonarbeiten |  | STB | 3.75 | 1163Unz0812903220 | Überzug | no | 0 | AllplanAttributes - Material Statik: STB; Positionsnummer_Text: U100
 | H2 Ebene +1 | STB | no | Betonarbeiten | E01 | STB | 3.75 | 1163Unz0812903103 | Überzug | no | 0 | AllplanAttributes - Material Statik: STB; Positionsnummer_Text: U100
 | H2 Ebene +1 | H | no | Zimmer- und Holzbauarbeiten |  | H | 3.75 | 1163Unz0812536552 | Unterzug | no | 0 | AllplanAttributes - Material Statik: FSH Baubuche GL75; Positionsnummer_Text: U36
 | H2 Ebene +1 | H | no | Zimmer- und Holzbauarbeiten |  | H | 3.75 | 1163Unz0812536504 | Unterzug | no | 0 | AllplanAttributes - Material Statik: FSH Baubuche GL75; Positionsnummer_Text: U36.1
 | H2 Ebene +1 | H | yes | Zimmer- und Holzbauarbeiten |  | H | 3.75 | 1163Unz0812536508 | Unterzug | no | 0 | AllplanAttributes - Material Statik: NH C24; Positionsnummer_Text: U21
 | H2 Ebene +1 | STB | no | Betonarbeiten | E01 | STB | 3.75 | 1163Unz0812903137 | Überzug | no | 0 | AllplanAttributes - Material Statik: STB; Positionsnummer_Text: U100
 | H2 Ebene +1 | STB | no | Betonarbeiten | E01 | STB | 3.75 | 1163Unz0812903163 | Überzug | no | 0 | AllplanAttributes - Material Statik: NH C24; Positionsnummer_Text: U100
 | H2 Ebene +1 | H | no | Zimmer- und Holzbauarbeiten |  | H | 3.75 | 1163Unz0813816056 | Unterzug | no | 0 | AllplanAttributes - Material Statik: FSH Baubuche GL75; Positionsnummer_Text: U100
 | H2 Ebene +1 | STB | no | Betonarbeiten | E01 | STB | 3.75 | 1163Unz0812903100 | Überzug | no | 0 | AllplanAttributes - Material Statik: STB; Positionsnummer_Text: U100
 | H2 Ebene +1 | H | yes | Zimmer- und Holzbauarbeiten |  | H | 3.75 | 1163Unz0812536510 | Unterzug | no | 0 | AllplanAttributes - Material Statik: NH C24; Positionsnummer_Text: U22
 | H2 Ebene +1 | STB | no | Betonarbeiten | E01 | STB | 3.75 | 1163Unz0812903180 | Überzug | no | 0 | AllplanAttributes - Material Statik: NH C24; Positionsnummer_Text: U100
 | H2 Ebene +1 | STB | no | Betonarbeiten | E01 | STB | 3.75 | 1163Unz0812903120 | Überzug | no | 0 | AllplanAttributes - Material Statik: NH C24; Positionsnummer_Text: U100
 | H2 Ebene +1 | H | yes | Zimmer- und Holzbauarbeiten |  | H | 3.75 | 1163Unz0812536512 | Unterzug | no | 0 | AllplanAttributes - Material Statik: NH C24; Positionsnummer_Text: U21
 | H2 Ebene +1 | H | no | Zimmer- und Holzbauarbeiten |  | H | 3.75 | 1163Unz0812746925 | Unterzug | no | 0 | AllplanAttributes - Material Statik: FSH Baubuche GL75; Positionsnummer_Text: U31
 | H2 Ebene +1 | H | no | Zimmer- und Holzbauarbeiten |  | H | 3.75 | 1163Unz0812536518 | Unterzug | no | 0 | AllplanAttributes - Material Statik: FSH Baubuche GL75; Positionsnummer_Text: U24
 | H2 Ebene +1 | H | no | Zimmer- und Holzbauarbeiten |  | H | 3.75 | 1163Unz0812536546 | Unterzug | no | 0 | AllplanAttributes - Material Statik: FSH Baubuche GL75; Positionsnummer_Text: U24
 | H2 Ebene +1 | H | no | Zimmer- und Holzbauarbeiten |  | H | 3.75 | 1163Unz0812747279 | Unterzug | no | 0 | AllplanAttributes - Material Statik: FSH Baubuche GL75; Positionsnummer_Text: U31
 | H2 Ebene +1 | H | yes | Zimmer- und Holzbauarbeiten |  | H | 3.75 | 1163Unz0812536516 | Unterzug | no | 0 | AllplanAttributes - Material Statik: NH C24; Positionsnummer_Text: U22
 | H2 Ebene +1 | STB | no | Betonarbeiten | E01 | STB | 3.75 | 1163Unz0812747607 | Überzug | no | 0 | AllplanAttributes - Material Statik: Stahlbeton; Positionsnummer_Text: U100
 | H2 Ebene +1 | STB | yes | Betonarbeiten |  | STB | 3.75 | 1163Unz0813718568 | Unterzug | no | 0 | AllplanAttributes - Positionsnummer_Text: U100; Sicherheitsklasse: -; Pset_BeamCommon - FireRating: 0
FS-Vorhang | H2 Ebene +1 |  | no | Zusatzgewerk Kunde |  | H | 0 | 1163Unz0814454114 | Brandschutzvorhang | no | 0 | AllplanAttributes - Text1: S200 C2; Bezeichnung: FS-Vorhang; Rauchschutz: yes; Selbstschließend: yes; Sicherheitsklasse: -; ash T_Tür-Nr.: FS-Vorhang; ash T_Raum zugehörigkeit: BS; Pset_BeamCommon - FireRating: EW60
FS-Vorhang | H2 Ebene +1 |  | no | Zusatzgewerk Kunde |  | H | 0 | 1163Unz0814454207 | Brandschutzvorhang | no | 0 | AllplanAttributes - Text1: S200 C2; Bezeichnung: FS-Vorhang; Rauchschutz: yes; Selbstschließend: yes; Sicherheitsklasse: -; ash T_Tür-Nr.: FS-Vorhang; ash T_Raum zugehörigkeit: BS; Pset_BeamCommon - FireRating: EW60
 | H2 Ebene +1 | STB | yes | Betonarbeiten | E01 | STB | 3.75 | 1163Unz0813663244 | Unterzug | no | 0 | AllplanAttributes - Positionsnummer_Text: U100; Sicherheitsklasse: -; Pset_BeamCommon - FireRating: 0
 | H2 Ebene +1 | STB | yes | Betonarbeiten |  | STB | 3.75 | 1163Unz0813663310 | Unterzug | no | 0 | AllplanAttributes - Positionsnummer_Text: U100; Sicherheitsklasse: -; Pset_BeamCommon - FireRating: 0
 | H2 Ebene +1 | STB | no | Betonarbeiten | E01 | STB | 3.75 | 1163Unz0812742174 | Überzug | no | 0 | AllplanAttributes - Material Statik: Stahlbeton; Positionsnummer_Text: U100
HEA160 | H2 Ebene +1 | SB-TRAEGER | yes | Stahlbauarbeiten |  | SB-TRAEGER |  | 1164Unz0000004370 | Stahlprofilträger | yes | 0.9 | AllplanAttributes - Bezeichnung: HEA160; Sicherheitsklasse: -; Schallschutzklasse: 32; Sonnenschutztyp: Movable; g-Wert: 0,51; Pset_BeamCommon - FireRating: 0
HEA160 | H2 Ebene +1 | SB-TRAEGER | yes | Stahlbauarbeiten |  | SB-TRAEGER |  | 1164Unz0000004382 | Stahlprofilträger | yes | 0.9 | AllplanAttributes - Bezeichnung: HEA160; Sicherheitsklasse: -; Schallschutzklasse: 32; Sonnenschutztyp: Movable; g-Wert: 0,51; Pset_BeamCommon - FireRating: 0
HEA160 | H2 Ebene +1 | SB-TRAEGER | yes | Stahlbauarbeiten |  | SB-TRAEGER |  | 1164Unz0000004397 | Stahlprofilträger | yes | 0.9 | AllplanAttributes - Bezeichnung: HEA160; Sicherheitsklasse: -; Schallschutzklasse: 32; Sonnenschutztyp: Movable; g-Wert: 0,51; Pset_BeamCommon - FireRating: 0
HEA160 | H2 Ebene +1 | SB-TRAEGER | yes | Stahlbauarbeiten |  | SB-TRAEGER |  | 1164Unz0000004403 | Stahlprofilträger | yes | 0.9 | AllplanAttributes - Bezeichnung: HEA160; Sicherheitsklasse: -; Schallschutzklasse: 32; Sonnenschutztyp: Movable; g-Wert: 0,51; Pset_BeamCommon - FireRating: 0
HEA160 | H2 Ebene +1 | SB-TRAEGER | yes | Stahlbauarbeiten |  | SB-TRAEGER |  | 1164Unz0000004400 | Stahlprofilträger | yes | 0.9 | AllplanAttributes - Bezeichnung: HEA160; Sicherheitsklasse: -; Schallschutzklasse: 32; Sonnenschutztyp: Movable; g-Wert: 0,51; Pset_BeamCommon - FireRating: 0
HEA160 | H2 Ebene +1 | SB-TRAEGER | yes | Stahlbauarbeiten |  | SB-TRAEGER |  | 1164Unz0000004406 | Stahlprofilträger | yes | 0.9 | AllplanAttributes - Bezeichnung: HEA160; Sicherheitsklasse: -; Schallschutzklasse: 32; Sonnenschutztyp: Movable; g-Wert: 0,51; Pset_BeamCommon - FireRating: 0
HEA160 | H2 Ebene +1 | SB-TRAEGER | yes | Stahlbauarbeiten |  | SB-TRAEGER |  | 1164Unz0000004385 | Stahlprofilträger | yes | 0.9 | AllplanAttributes - Bezeichnung: HEA160; Sicherheitsklasse: -; Schallschutzklasse: 32; Sonnenschutztyp: Movable; g-Wert: 0,51; Pset_BeamCommon - FireRating: 0
HEA160 | H2 Ebene +1 | SB-TRAEGER | yes | Stahlbauarbeiten |  | SB-TRAEGER |  | 1164Unz0000004364 | Stahlprofilträger | yes | 0.9 | AllplanAttributes - Bezeichnung: HEA160; Sicherheitsklasse: -; Schallschutzklasse: 32; Sonnenschutztyp: Movable; g-Wert: 0,51; Pset_BeamCommon - FireRating: 0
 | H2 Ebene 0 | BS Bekleidung | yes | Zimmer- und Holzbauarbeiten | E00 | BS Bekleidung | 0 | 1105Kop0811459225 | Mengenkörper | no | 0 | AllplanAttributes - Material Architektur: Gipsfaserplatten 2-lagig (BSK)
 | H2 Ebene 0 | BS Bekleidung | yes | Zimmer- und Holzbauarbeiten | E00 | BS Bekleidung | 0 | 1105Kop0811459217 | Mengenkörper | no | 0 | AllplanAttributes - Material Architektur: Gipsfaserplatten 2-lagig (BSK)
 | H2 Ebene 0 | BS Bekleidung | yes | Zimmer- und Holzbauarbeiten | E00 | BS Bekleidung | 0 | 1105Kop0811459213 | Mengenkörper | no | 0 | AllplanAttributes - Material Architektur: Gipsfaserplatten 2-lagig (BSK)
 | H2 Ebene 0 | H | no | Zimmer- und Holzbauarbeiten |  | H | 0 | 1105Unz0000001998 | Unterzug | no | 0 | AllplanAttributes - Positionsnummer_Text: U23; Sicherheitsklasse: -; Pset_BeamCommon - FireRating: 0
 | H2 Ebene 0 | H | no | Zimmer- und Holzbauarbeiten |  | H | 0 | 1105Unz0000002541 | Unterzug | no | 0 | AllplanAttributes - Positionsnummer_Text: U23; Sicherheitsklasse: -; Pset_BeamCommon - FireRating: 0
 | H2 Ebene 0 | H | no | Zimmer- und Holzbauarbeiten |  | H | 0 | 1105Unz0000084433 | Unterzug | no | 0 | AllplanAttributes - Material Statik: NH C24; Positionsnummer_Text: U23; Sicherheitsklasse: -; Pset_BeamCommon - FireRating: 0
 | H2 Ebene 0 | BS Bekleidung | yes | Zimmer- und Holzbauarbeiten | E00 | BS Bekleidung | 0 | 1113Kop0812956613 | Stahlprofilträger | no | 0 | AllplanAttributes - Material Architektur: Gipsfaserplatten 2-lagig (BSK)
HEA140 | H2 Ebene 0 | HEA140 | yes | Stahlbauarbeiten |  | HEA140 | 0 | 1113Unz0813892701 | Stahlprofilträger | yes | AllplanAttributes - Positionsnummer_Text: U26; Bezeichnung: HEA140; Sicherheitsklasse: -; Pset_BeamCommon - FireRating: REI 90-A1
HEA240 | H2 Ebene 0 | HEA240 | yes | Stahlbauarbeiten |  | HEA240 | 0 | 1113Unz0812747129 | Stahlprofilträger | yes | AllplanAttributes - Positionsnummer_Text: U28; Bezeichnung: HEA240; Sicherheitsklasse: -; Pset_BeamCommon - FireRating: REI 90-A1
HEA240 | H2 Ebene 0 | HEA240 | yes | Stahlbauarbeiten |  | HEA240 | 0 | 1113Unz0812746991 | Stahlprofilträger | yes | AllplanAttributes - Positionsnummer_Text: U28; Bezeichnung: HEA240; Sicherheitsklasse: -; Pset_BeamCommon - FireRating: REI 90-A1
HEA140 | H2 Ebene 0 | HEA140 | yes | Stahlbauarbeiten |  | HEA140 | 0 | 1113Unz0812747270 | Stahlprofilträger | yes | AllplanAttributes - Positionsnummer_Text: U26; Bezeichnung: HEA140; Sicherheitsklasse: -; Pset_BeamCommon - FireRating: REI 90-A1
HEA240 | H2 Ebene 0 | HEA240 | yes | Stahlbauarbeiten |  | HEA240 | 0 | 1113Unz0812747122 | Stahlprofilträger | yes | AllplanAttributes - Positionsnummer_Text: U34; Bezeichnung: HEA240; Sicherheitsklasse: -; Pset_BeamCommon - FireRating: REI 90-A1
HEA240 | H2 Ebene 0 | HEA240 | yes | Stahlbauarbeiten |  | HEA240 | 0 | 1113Unz0812746965 | Stahlprofilträger | yes | AllplanAttributes - Positionsnummer_Text: U33; Bezeichnung: HEA240; Sicherheitsklasse: -; Pset_BeamCommon - FireRating: REI 90-A1
HEA240 | H2 Ebene 0 | HEA240 | yes | Stahlbauarbeiten |  | HEA240 | 0 | 1113Unz0812833047 | Stahlprofilträger | yes | AllplanAttributes - Positionsnummer_Text: U27; Bezeichnung: HEA240; Sicherheitsklasse: -; Pset_BeamCommon - FireRating: REI 90-A1
HEA140 | H2 Ebene 0 | HEA140 | yes | Stahlbauarbeiten |  | HEA140 | 0 | 1113Unz0812747028 | Stahlprofilträger | yes | AllplanAttributes - Positionsnummer_Text: U26; Bezeichnung: HEA140; Sicherheitsklasse: -; Pset_BeamCommon - FireRating: REI 90-A1
HEA240 | H2 Ebene 0 | HEA240 | yes | Stahlbauarbeiten |  | HEA240 | 0 | 1113Unz0812746961 | Stahlprofilträger | yes | AllplanAttributes - Positionsnummer_Text: U32; Bezeichnung: HEA240; Sicherheitsklasse: -; Pset_BeamCommon - FireRating: REI 90-A1
HEA240 | H2 Ebene 0 | HEA240 | yes | Stahlbauarbeiten |  | HEA240 | 0 | 1113Unz0813892526 | Stahlprofilträger | yes | AllplanAttributes - Positionsnummer_Text: U28; Bezeichnung: HEA240; Sicherheitsklasse: -; Pset_BeamCommon - FireRating: REI 90-A1
HEA240 | H2 Ebene 0 | HEA240 | yes | Stahlbauarbeiten |  | HEA240 | 0 | 1113Unz0813892611 | Stahlprofilträger | yes | AllplanAttributes - Positionsnummer_Text: U28; Bezeichnung: HEA240; Sicherheitsklasse: -; Pset_BeamCommon - FireRating: REI 90-A1
HEA140 | H2 Ebene 0 | HEA140 | yes | Stahlbauarbeiten |  | HEA140 | 0 | 1113Unz0812746839 | Stahlprofilträger | yes | AllplanAttributes - Positionsnummer_Text: U25; Bezeichnung: HEA140; Sicherheitsklasse: -; Pset_BeamCommon - FireRating: REI 90-A1
 | H2 Ebene 0 | BS Bekleidung | yes | Zimmer- und Holzbauarbeiten | E00 | BS Bekleidung | 0 | 1113Kop0812947023 | Mengenkörper | no | 0 | AllplanAttributes - Material Architektur: Gipsfaserplatten 2-lagig (BSK)
 | H2 Ebene 0 | BS Bekleidung | yes | Zimmer- und Holzbauarbeiten | E00 | BS Bekleidung | 0 | 1113Kop0812946990 | Mengenkörper | no | 0 | AllplanAttributes - Material Architektur: Gipsfaserplatten 2-lagig (BSK)
 | H2 Ebene 0 | BS Bekleidung | yes | Zimmer- und Holzbauarbeiten | E00 | BS Bekleidung | 0 | 1113Kop0812946981 | Mengenkörper | no | 0 | AllplanAttributes - Material Architektur: Gipsfaserplatten 2-lagig (BSK)
 | H2 Ebene 0 | BS Bekleidung | yes | Zimmer- und Holzbauarbeiten | E00 | BS Bekleidung | 0 | 1113Kop0812946984 | Mengenkörper | no | 0 | AllplanAttributes - Material Architektur: Gipsfaserplatten 2-lagig (BSK)
 | H2 Ebene 0 | BS Bekleidung | yes | Zimmer- und Holzbauarbeiten | E00 | BS Bekleidung | 0 | 1113Kop0812946978 | Mengenkörper | no | 0 | AllplanAttributes - Material Architektur: Gipsfaserplatten 2-lagig (BSK)
 | H2 Ebene 0 | BS Bekleidung | yes | Zimmer- und Holzbauarbeiten | E00 | BS Bekleidung | 0 | 1113Kop0812946963 | Mengenkörper | no | 0 | AllplanAttributes - Material Architektur: Gipsfaserplatten 2-lagig (BSK)
 | H2 Ebene 0 | BS Bekleidung | yes | Zimmer- und Holzbauarbeiten | E00 | BS Bekleidung | 0 | 1113Kop0812946969 | Mengenkörper | no | 0 | AllplanAttributes - Material Architektur: Gipsfaserplatten 2-lagig (BSK)
 | H2 Ebene 0 | BS Bekleidung | yes | Zimmer- und Holzbauarbeiten | E00 | BS Bekleidung | 0 | 1113Kop0812947026 | Mengenkörper | no | 0 | AllplanAttributes - Material Architektur: Gipsfaserplatten 2-lagig (BSK)
 | H2 Ebene 0 | BS Bekleidung | yes | Zimmer- und Holzbauarbeiten | E00 | BS Bekleidung | 0 | 1113Kop0812947020 | Mengenkörper | no | 0 | AllplanAttributes - Material Architektur: Gipsfaserplatten 2-lagig (BSK)
 | H2 Ebene 0 | BS Bekleidung | yes | Zimmer- und Holzbauarbeiten | E00 | BS Bekleidung | 0 | 1113Kop0812947029 | Mengenkörper | no | 0 | AllplanAttributes - Material Architektur: Gipsfaserplatten 2-lagig (BSK)
 | H2 Ebene 0 | BS Bekleidung | yes | Zimmer- und Holzbauarbeiten | E00 | BS Bekleidung | 0 | 1113Kop0812947032 | Mengenkörper | no | 0 | AllplanAttributes - Material Architektur: Gipsfaserplatten 2-lagig (BSK)
 | H2 Ebene 0 | BS Bekleidung | yes | Zimmer- und Holzbauarbeiten | E01 | BS Bekleidung | 3.75 | 1113Kop0813939219 | Mengenkörper | no | 0 | AllplanAttributes - Material Architektur: Gipsfaserplatten 2-lagig (BSK)
 | H2 Ebene 0 | BS Bekleidung | yes | Zimmer- und Holzbauarbeiten | E00 | BS Bekleidung | 0 | 1113Kop0812946987 | Mengenkörper | no | 0 | AllplanAttributes - Material Architektur: Gipsfaserplatten 2-lagig (BSK)
 | H2 Ebene 0 | BS Bekleidung | yes | Zimmer- und Holzbauarbeiten | E00 | BS Bekleidung | 0 | 1113Kop0812947017 | Mengenkörper | no | 0 | AllplanAttributes - Material Architektur: Gipsfaserplatten 2-lagig (BSK)
 | H2 Ebene 0 | BS Bekleidung | yes | Zimmer- und Holzbauarbeiten | E00 | BS Bekleidung | 0 | 1113Kop0812947002 | Mengenkörper | no | 0 | AllplanAttributes - Material Architektur: Gipsfaserplatten 2-lagig (BSK)
 | H2 Ebene 0 | BS Bekleidung | yes | Zimmer- und Holzbauarbeiten | E00 | BS Bekleidung | 0 | 1113Kop0812946996 | Mengenkörper | no | 0 | AllplanAttributes - Material Architektur: Gipsfaserplatten 2-lagig (BSK)
 | H2 Ebene 0 | BS Bekleidung | yes | Zimmer- und Holzbauarbeiten | E00 | BS Bekleidung | 0 | 1113Kop0812947011 | Mengenkörper | no | 0 | AllplanAttributes - Material Architektur: Gipsfaserplatten 2-lagig (BSK)
 | H2 Ebene 0 | BS Bekleidung | yes | Zimmer- und Holzbauarbeiten | E00 | BS Bekleidung | 0 | 1113Kop0812946975 | Mengenkörper | no | 0 | AllplanAttributes - Material Architektur: Gipsfaserplatten 2-lagig (BSK)
 | H2 Ebene 0 | BS Bekleidung | yes | Zimmer- und Holzbauarbeiten | E00 | BS Bekleidung | 0 | 1113Kop0812946972 | Mengenkörper | no | 0 | AllplanAttributes - Material Architektur: Gipsfaserplatten 2-lagig (BSK)
 | H2 Ebene 0 | BS Bekleidung | yes | Zimmer- und Holzbauarbeiten | E00 | BS Bekleidung | 0 | 1113Kop0812947050 | Mengenkörper | no | 0 | AllplanAttributes - Material Architektur: Gipsfaserplatten 2-lagig (BSK)
 | H2 Ebene 0 | BS Bekleidung | yes | Zimmer- und Holzbauarbeiten | E00 | BS Bekleidung | 0 | 1113Kop0812947008 | Mengenkörper | no | 0 | AllplanAttributes - Material Architektur: Gipsfaserplatten 2-lagig (BSK)
 | H2 Ebene 0 | BS Bekleidung | yes | Zimmer- und Holzbauarbeiten | E00 | BS Bekleidung | 0 | 1113Kop0812947014 | Mengenkörper | no | 0 | AllplanAttributes - Material Architektur: Gipsfaserplatten 2-lagig (BSK)
 | H2 Ebene 0 | BS Bekleidung | yes | Zimmer- und Holzbauarbeiten | E00 | BS Bekleidung | 0 | 1113Kop0812947035 | Mengenkörper | no | 0 | AllplanAttributes - Material Architektur: Gipsfaserplatten 2-lagig (BSK)
 | H2 Ebene 0 | BS Bekleidung | yes | Zimmer- und Holzbauarbeiten | E00 | BS Bekleidung | 0 | 1113Kop0812946966 | Mengenkörper | no | 0 | AllplanAttributes - Material Architektur: Gipsfaserplatten 2-lagig (BSK)
 | H2 Ebene 0 | H | yes | Zimmer- und Holzbauarbeiten |  | H | 0 | 1113Unz0812536514 | Unterzug | no | 0 | AllplanAttributes - Material Statik: FSH Baubuche GL75; Positionsnummer_Text: U20; Sicherheitsklasse: -
 | H2 Ebene 0 | H | no | Zimmer- und Holzbauarbeiten |  | H | 0 | 1113Unz0812536504 | Unterzug | no | 0 | AllplanAttributes - Material Statik: FSH Baubuche GL75; Positionsnummer_Text: U36.1; Sicherheitsklasse: -
 | H2 Ebene 0 | H | yes | Zimmer- und Holzbauarbeiten |  | H | 0 | 1113Unz0812536508 | Unterzug | no | 0 | AllplanAttributes - Material Statik: NH C24; Positionsnummer_Text: U21; Sicherheitsklasse: -
 | H2 Ebene 0 | H | yes | Zimmer- und Holzbauarbeiten |  | H | 0 | 1113Unz0812536510 | Unterzug | no | 0 | AllplanAttributes - Material Statik: NH C24; Positionsnummer_Text: U22; Sicherheitsklasse: -
 | H2 Ebene 0 | H | no | Zimmer- und Holzbauarbeiten |  | H | 0 | 1113Unz0812747279 | Unterzug | no | 0 | AllplanAttributes - Material Statik: FSH Baubuche GL75; Positionsnummer_Text: U31; Sicherheitsklasse: -
 | H2 Ebene 0 | H | no | Zimmer- und Holzbauarbeiten |  | H | 0 | 1113Unz0812746925 | Unterzug | no | 0 | AllplanAttributes - Material Statik: FSH Baubuche GL75; Positionsnummer_Text: U31; Sicherheitsklasse: -
 | H2 Ebene 0 | H | no | Zimmer- und Holzbauarbeiten |  | H | 0 | 1113Unz0812536518 | Unterzug | no | 0 | AllplanAttributes - Material Statik: FSH Baubuche GL75; Positionsnummer_Text: U24; Sicherheitsklasse: -
 | H2 Ebene 0 | H | no | Zimmer- und Holzbauarbeiten |  | H | 0 | 1113Unz0812536546 | Unterzug | no | 0 | AllplanAttributes - Material Statik: FSH Baubuche GL75; Positionsnummer_Text: U24; Sicherheitsklasse: -
 | H2 Ebene 0 | H | no | Zimmer- und Holzbauarbeiten |  | H | 3.75 | 1113Unz0813939247 | Unterzug | no | 0 | AllplanAttributes - Material Statik: FSH Baubuche GL75; Positionsnummer_Text: U100
 | H2 Ebene 0 | H | yes | Zimmer- und Holzbauarbeiten |  | H | 0 | 1113Unz0812536506 | Unterzug | no | 0 | AllplanAttributes - Material Statik: FSH Baubuche GL75; Positionsnummer_Text: U20; Sicherheitsklasse: -
 | H2 Ebene 0 | H | yes | Zimmer- und Holzbauarbeiten |  | H | 0 | 1113Unz0812536512 | Unterzug | no | 0 | AllplanAttributes - Material Statik: NH C24; Positionsnummer_Text: U21; Sicherheitsklasse: -
 | H2 Ebene 0 | H | no | Zimmer- und Holzbauarbeiten |  | H | 0 | 1113Unz0812536552 | Unterzug | no | 0 | AllplanAttributes - Material Statik: FSH Baubuche GL75; Positionsnummer_Text: U36; Sicherheitsklasse: -
 | H2 Ebene 0 | H | yes | Zimmer- und Holzbauarbeiten |  | H | 0 | 1113Unz0812536516 | Unterzug | no | 0 | AllplanAttributes - Material Statik: NH C24; Positionsnummer_Text: U22; Sicherheitsklasse: -
 | H2 Ebene 0 | STB | no | Betonarbeiten |  | STB | 0 | 1113Unz0812747607 | Überzug | no | 0 | AllplanAttributes - Material Statik: Stahlbeton; Positionsnummer_Text: U101; Sicherheitsklasse: -
 | H2 Ebene 0 | STB | yes | Betonarbeiten |  | STB | 0 | 1113Unz0812941791 | Unterzug | no | 0 | AllplanAttributes - Positionsnummer_Text: U40; Sicherheitsklasse: -; Pset_BeamCommon - FireRating: 0
 | H2 Ebene 0 | STB | yes | Betonarbeiten |  | STB | 0 | 1113Unz0812941779 | Unterzug | no | 0 | AllplanAttributes - Positionsnummer_Text: U38; Sicherheitsklasse: -; Pset_BeamCommon - FireRating: 0
FS-Vorhang | H2 Ebene 0 |  | no | Zusatzgewerk Kunde |  | H | 0 | 1113Unz0813933630 | Brandschutzvorhang | no | 0 | AllplanAttributes - Text1: S200 C2; Bezeichnung: FS-Vorhang; Rauchschutz: yes; Selbstschließend: yes; Sicherheitsklasse: -; ash T_Tür-Nr.: FS-Vorhang; ash T_Raum zugehörigkeit: BS; Pset_BeamCommon - FireRating: EI2 60
FS-Vorhang | H2 Ebene 0 |  | no | Zusatzgewerk Kunde |  | H | 0 | 1113Unz0813933492 | Brandschutzvorhang | no | 0 | AllplanAttributes - Text1: S200 C2; Bezeichnung: FS-Vorhang; Rauchschutz: yes; Selbstschließend: yes; Sicherheitsklasse: -; ash T_Tür-Nr.: FS-Vorhang; ash T_Raum zugehörigkeit: BS; Pset_BeamCommon - FireRating: EW60
 | H2 Ebene 0 | STB | yes | Betonarbeiten |  | STB | 0 | 1113Unz0812941809 | Unterzug | no | 0 | AllplanAttributes - Positionsnummer_Text: U41; Sicherheitsklasse: -; Pset_BeamCommon - FireRating: 0
 | H2 Ebene 0 | STB | yes | Betonarbeiten |  | STB | 0 | 1113Unz0812942131 | Unterzug | no | 0 | AllplanAttributes - Positionsnummer_Text: U40; Sicherheitsklasse: -; Pset_BeamCommon - FireRating: 0
 | H2 Ebene 0 | STB | no | Betonarbeiten |  | STB | 0 | 1113Unz0812742174 | Überzug | no | 0 | AllplanAttributes - Material Statik: Stahlbeton; Positionsnummer_Text: U101; Sicherheitsklasse: -
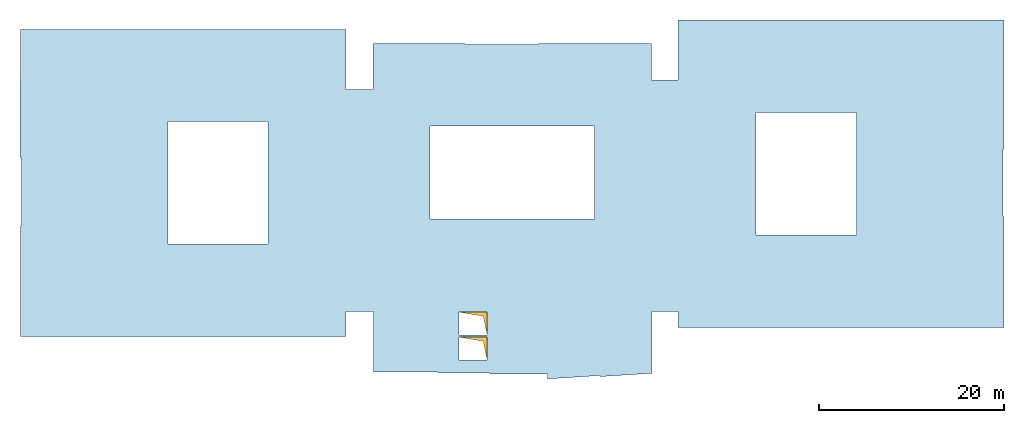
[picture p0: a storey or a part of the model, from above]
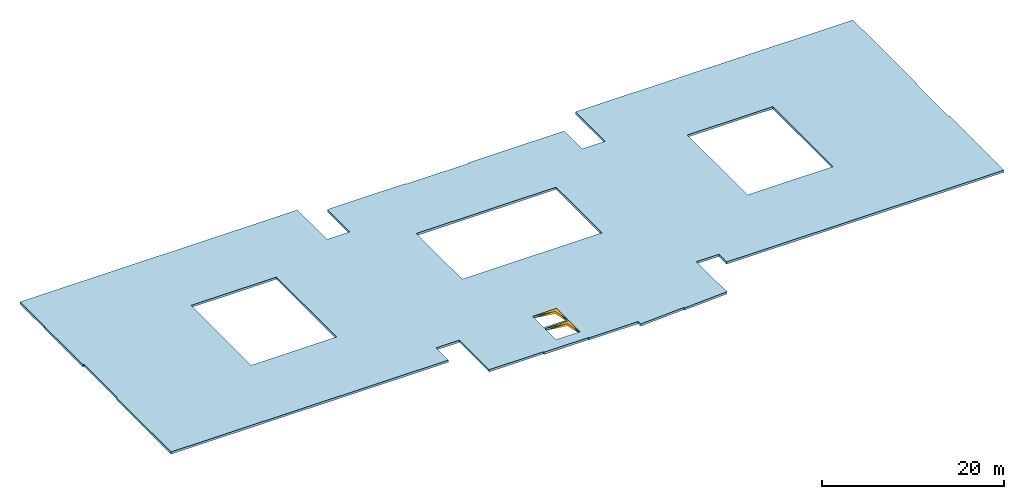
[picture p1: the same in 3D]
Properties of the parts of a building model (IFC4), part 4 of 80

# IfcBeam (310)
Name | In | Material | 2D Interaktion | Gewerk | Ortscode_Geschoßbezeichnung | AllplanAttributes, Material | OKFF | Allright_Bauteil_ID | Objektname | IsExternal | ThermalTransmittance (W/K/m2)
HEA160 | H2 Ebene 0 | SB-TRAEGER | yes | Stahlbauarbeiten |  | SB-TRAEGER |  | 1114Unz0000004255 | Stahlprofilträger | yes | AllplanAttributes - Bezeichnung: HEA160; Pset_BeamCommon - FireRating: REI 90-A1
HEA160 | H2 Ebene 0 | SB-TRAEGER | yes | Stahlbauarbeiten |  | SB-TRAEGER |  | 1114Unz0000004321 | Stahlprofilträger | yes | AllplanAttributes - Bezeichnung: HEA160; Pset_BeamCommon - FireRating: REI 90-A1
HEA160 | H2 Ebene 0 | SB-TRAEGER | yes | Stahlbauarbeiten |  | SB-TRAEGER |  | 1114Unz0000004289 | Stahlprofilträger | yes | AllplanAttributes - Bezeichnung: HEA160; Pset_BeamCommon - FireRating: REI 90-A1
HEA160 | H2 Ebene 0 | SB-TRAEGER | yes | Stahlbauarbeiten |  | SB-TRAEGER |  | 1114Unz0000004315 | Stahlprofilträger | yes | AllplanAttributes - Bezeichnung: HEA160; Pset_BeamCommon - FireRating: REI 90-A1
HEA160 | H2 Ebene 0 | SB-TRAEGER | yes | Stahlbauarbeiten |  | SB-TRAEGER |  | 1114Unz0000004286 | Stahlprofilträger | yes | AllplanAttributes - Bezeichnung: HEA160; Pset_BeamCommon - FireRating: REI 90-A1
HEA160 | H2 Ebene 0 | SB-TRAEGER | yes | Stahlbauarbeiten |  | SB-TRAEGER |  | 1114Unz0000004237 | Stahlprofilträger | yes | AllplanAttributes - Bezeichnung: HEA160; Pset_BeamCommon - FireRating: REI 90-A1
HEA160 | H2 Ebene 0 | SB-TRAEGER | yes | Stahlbauarbeiten |  | SB-TRAEGER |  | 1114Unz0000004249 | Stahlprofilträger | yes | AllplanAttributes - Bezeichnung: HEA160; Pset_BeamCommon - FireRating: REI 90-A1
HEA160 | H2 Ebene 0 | SB-TRAEGER | yes | Stahlbauarbeiten |  | SB-TRAEGER |  | 1114Unz0000004243 | Stahlprofilträger | yes | AllplanAttributes - Bezeichnung: HEA160; Pset_BeamCommon - FireRating: REI 90-A1

# IfcBuildingElementProxy (257)
Name | In | Allright_Bauteil_ID | Abrechnungsart | Objektname | Material = AllplanAttributes, Material | Gewerk
Nullpunkt | Modellreferenzen | 5981Mak0000010864 | St | Makro | AllplanAttributes - UK: 0 m; OK: 0 m; V6: 0 m; V7: 0 m; V8: 0 m; V9: 0; Bezeichnung: Nullpunkt
38 x  | H2 Ebene +4/ Dachebene
 | H2 Ebene +3 | 1255Veb0811534271 | m² | Verblendung | WA-HS | Zimmer- und Holzbauarbeiten
 | H2 Ebene +3 | 1255Veb0811534328 | m² | Verblendung | WA-HS | Zimmer- und Holzbauarbeiten
 | H2 Ebene +3 | 1255Veb0811534444 | m² | Verblendung | WA-HS | Zimmer- und Holzbauarbeiten
 | H2 Ebene +3 | 1255Veb0811534387 | m² | Verblendung | WA-HS | Zimmer- und Holzbauarbeiten
 | H2 Ebene +3 | 1255Veb0811534200 | m² | Verblendung | WA-HS | Zimmer- und Holzbauarbeiten
 | H2 Ebene +3 | 1255Veb0811534017 | m² | Verblendung | Fensterelement | Zimmer- und Holzbauarbeiten
 | H2 Ebene +3 | 1255Veb0811537000 | m² | Verblendung | Fensterelement | Zimmer- und Holzbauarbeiten
 | H2 Ebene +3 | 1255Veb0811537734 | m² | Verblendung | WA-HS | Zimmer- und Holzbauarbeiten
 | H2 Ebene +3 | 1255Veb0811537650 | m² | Verblendung | WA-HS | Zimmer- und Holzbauarbeiten
 | H2 Ebene +3 | 1255Veb0811535938 | m² | Verblendung | Fensterelement | Zimmer- und Holzbauarbeiten
 | H2 Ebene +3 | 1255Veb0811536108 | m² | Verblendung | Fensterelement | Zimmer- und Holzbauarbeiten
 | H2 Ebene +3 | 1255Veb0811537282 | m² | Verblendung | WA-HS | Zimmer- und Holzbauarbeiten
 | H2 Ebene +3 | 1255Veb0811537335 | m² | Verblendung | WA-HS | Zimmer- und Holzbauarbeiten
 | H2 Ebene +3 | 1255Veb0811537483 | m² | Verblendung | WA-HS | Zimmer- und Holzbauarbeiten
26 x  | H2 Ebene +3
Symbol BD | H2 Ebene +3 | 1263Mak0812974996 | St | Bodendurchbruchsmakro | AllplanAttributes - V6: 0 m; V7: 0 m; V8: 0 m; V9: 0; Bezeichnung: Symbol BD; Programmversion: 3.0; Plugin_Bezeichnung: MainObject; Plugin_Objektname: SmartPartCompressed; Version: 1.0; Attributset-Objekt: Opening
Symbol BD | H2 Ebene +3 | 1263Mak0812974997 | St | Bodendurchbruchsmakro | AllplanAttributes - V6: 0 m; V7: 0 m; V8: 0 m; V9: 0; Bezeichnung: Symbol BD; Programmversion: 3.0; Plugin_Bezeichnung: MainObject; Plugin_Objektname: SmartPartCompressed; Version: 1.0; Attributset-Objekt: Opening
 | H2 Ebene +2 | 1205Veb0000349696 | m² | Verblendung | WA-HS | Zimmer- und Holzbauarbeiten
 | H2 Ebene +2 | 1205Veb0000347408 | m² | Verblendung | WA-HS | Zimmer- und Holzbauarbeiten
 | H2 Ebene +2 | 1205Veb0000347848 | m² | Verblendung | WA-HS | Zimmer- und Holzbauarbeiten
 | H2 Ebene +2 | 1205Veb0000348055 | m² | Verblendung | WA-HS | Zimmer- und Holzbauarbeiten
 | H2 Ebene +2 | 1205Veb0000349346 | m² | Verblendung | WA-HS | Zimmer- und Holzbauarbeiten
 | H2 Ebene +2 | 1205Veb0000349101 | m² | Verblendung | WA-HS | Zimmer- und Holzbauarbeiten
 | H2 Ebene +2 | 1205Veb0000346739 | m² | Verblendung | WA-HS | Zimmer- und Holzbauarbeiten
 | H2 Ebene +2 | 1205Veb0000346123 | m² | Verblendung | WA-HS | Zimmer- und Holzbauarbeiten
 | H2 Ebene +2 | 1205Veb0000345050 | m² | Verblendung | WA-HS | Zimmer- und Holzbauarbeiten
 | H2 Ebene +2 | 1205Veb0000345565 | m² | Verblendung | WA-HS | Zimmer- und Holzbauarbeiten
 | H2 Ebene +2 | 1205Veb0000346385 | m² | Verblendung | WA-HS | Zimmer- und Holzbauarbeiten
 | H2 Ebene +2 | 1205Veb0000356365 | m² | Verblendung | WA-HS | Zimmer- und Holzbauarbeiten
 | H2 Ebene +2 | 1205Veb2005819451 | m² | Verblendung | WA-HS | Zimmer- und Holzbauarbeiten
 | H2 Ebene +2 | 1205Veb2005818865 | m² | Verblendung | WA-HS | Zimmer- und Holzbauarbeiten
 | H2 Ebene +2 | 1205Veb2005819304 | m² | Verblendung | WA-HS | Zimmer- und Holzbauarbeiten
 | H2 Ebene +2 | 1205Veb2005823955 | m² | Verblendung | WA-HS | Zimmer- und Holzbauarbeiten
 | H2 Ebene +2 | 1205Veb2005829416 | m² | Verblendung | WA-HS | Zimmer- und Holzbauarbeiten
 | H2 Ebene +2 | 1205Veb2005828719 | m² | Verblendung | WA-HS | Zimmer- und Holzbauarbeiten
 | H2 Ebene +2 | 1205Veb2005828042 | m² | Verblendung | WA-HS | Zimmer- und Holzbauarbeiten
 | H2 Ebene +2 | 1205Veb2005828386 | m² | Verblendung | WA-HS | Zimmer- und Holzbauarbeiten
 | H2 Ebene +2 | 1205Veb2005829780 | m² | Verblendung | WA-HS | Zimmer- und Holzbauarbeiten
 | H2 Ebene +2 | 1205Veb2005829073 | m² | Verblendung | WA-HS | Zimmer- und Holzbauarbeiten
 | H2 Ebene +2 | 1205Veb2005824554 | m² | Verblendung | WA-HS | Zimmer- und Holzbauarbeiten
 | H2 Ebene +2 | 1205Veb2005824456 | m² | Verblendung | WA-HS | Zimmer- und Holzbauarbeiten
 | H2 Ebene +2 | 1205Veb2005819678 | m² | Verblendung | WA-HS | Zimmer- und Holzbauarbeiten
 | H2 Ebene +2 | 1205Veb2005819535 | m² | Verblendung | WA-HS | Zimmer- und Holzbauarbeiten
 | H2 Ebene +2 | 1205Veb2005827160 | m² | Verblendung | WA-HS | Zimmer- und Holzbauarbeiten
 | H2 Ebene +2 | 1205Veb2005826707 | m² | Verblendung | WA-HS | Zimmer- und Holzbauarbeiten
 | H2 Ebene +2 | 1205Veb2005825957 | m² | Verblendung | WA-HS | Zimmer- und Holzbauarbeiten
 | H2 Ebene +2 | 1205Veb2005826434 | m² | Verblendung | WA-HS | Zimmer- und Holzbauarbeiten
 | H2 Ebene +2 | 1205Veb2005826933 | m² | Verblendung | WA-HS | Zimmer- und Holzbauarbeiten
 | H2 Ebene +2 | 1205Veb2005824860 | m² | Verblendung | WA-HS | Zimmer- und Holzbauarbeiten
 | H2 Ebene +2 | 1205Veb0000347231 | m² | Verblendung | WA-HS | Zimmer- und Holzbauarbeiten
 | H2 Ebene +2 | 1205Veb0000347142 | m² | Verblendung | WA-HS | Zimmer- und Holzbauarbeiten
 | H2 Ebene +2 | 1205Veb0000346991 | m² | Verblendung | WA-HS | Zimmer- und Holzbauarbeiten
 | H2 Ebene +2 | 1205Veb0000347322 | m² | Verblendung | WA-HS | Zimmer- und Holzbauarbeiten
 | H2 Ebene +2 | 1205Veb0000358294 | m² | Verblendung | WA-HS | Zimmer- und Holzbauarbeiten
 | H2 Ebene +2 | 1205Veb2005816909 | m² | Verblendung | WA-HS | Zimmer- und Holzbauarbeiten
 | H2 Ebene +2 | 1205Veb2005817066 | m² | Verblendung | WA-HS | Zimmer- und Holzbauarbeiten
 | H2 Ebene +2 | 1205Veb2005817143 | m² | Verblendung | WA-HS | Zimmer- und Holzbauarbeiten
 | H2 Ebene +2 | 1205Veb2005825858 | m² | Verblendung | WA-HS | Zimmer- und Holzbauarbeiten
 | H2 Ebene +2 | 1205Veb2005825776 | m² | Verblendung | WA-HS | Zimmer- und Holzbauarbeiten
 | H2 Ebene +2 | 1205Veb2005825694 | m² | Verblendung | WA-HS | Zimmer- und Holzbauarbeiten
 | H2 Ebene +2 | 1205Veb2005825468 | m² | Verblendung | WA-HS | Zimmer- und Holzbauarbeiten
 | H2 Ebene +2 | 1205Veb2005827876 | m² | Verblendung | WA-HS | Zimmer- und Holzbauarbeiten
 | H2 Ebene +2 | 1205Veb2005827546 | m² | Verblendung | WA-HS | Zimmer- und Holzbauarbeiten
 | H2 Ebene +2 | 1205Veb2005827670 | m² | Verblendung | WA-HS | Zimmer- und Holzbauarbeiten
 | H2 Ebene +2 | 1205Veb2005827774 | m² | Verblendung | WA-HS | Zimmer- und Holzbauarbeiten
 | H2 Ebene +2 | 1205Veb2005859220 | m² | Verblendung | WA-HS | Zimmer- und Holzbauarbeiten
 | H2 Ebene +2 | 1205Veb2005859497 | m² | Verblendung | WA-HS | Zimmer- und Holzbauarbeiten
 | H2 Ebene +2 | 1205Veb2005859388 | m² | Verblendung | WA-HS | Zimmer- und Holzbauarbeiten
 | H2 Ebene +2 | 1205Veb2005859131 | m² | Verblendung | WA-HS | Zimmer- und Holzbauarbeiten
 | H2 Ebene +2 | 1205Veb2005859042 | m² | Verblendung | WA-HS | Zimmer- und Holzbauarbeiten
4 x  | H2 Ebene +2
 | H2 Ebene +1 | 1155Veb2005776062 | m² | Verblendung | WA-HS | Zimmer- und Holzbauarbeiten
 | H2 Ebene +1 | 1155Veb2005774569 | m² | Verblendung | WA-HS | Zimmer- und Holzbauarbeiten
 | H2 Ebene +1 | 1155Veb2005775012 | m² | Verblendung | WA-HS | Zimmer- und Holzbauarbeiten
 | H2 Ebene +1 | 1155Veb2005774150 | m² | Verblendung | WA-HS | Zimmer- und Holzbauarbeiten
 | H2 Ebene +1 | 1155Veb2005773926 | m² | Verblendung | WA-HS | Zimmer- und Holzbauarbeiten
 | H2 Ebene +1 | 1155Veb2005774358 | m² | Verblendung | WA-HS | Zimmer- und Holzbauarbeiten
 | H2 Ebene +1 | 1155Veb2005719593 | m² | Verblendung | WA-HS | Zimmer- und Holzbauarbeiten
 | H2 Ebene +1 | 1155Veb2005719411 | m² | Verblendung | WA-HS | Zimmer- und Holzbauarbeiten
 | H2 Ebene +1 | 1155Veb2005719860 | m² | Verblendung | WA-HS | Zimmer- und Holzbauarbeiten
 | H2 Ebene +1 | 1155Veb2005717255 | m² | Verblendung | WA-HS | Zimmer- und Holzbauarbeiten
 | H2 Ebene +1 | 1155Veb2005718904 | m² | Verblendung | WA-HS | Zimmer- und Holzbauarbeiten
 | H2 Ebene +1 | 1155Veb2005783785 | m² | Verblendung | WA-HS | Zimmer- und Holzbauarbeiten
 | H2 Ebene +1 | 1155Veb2005796991 | m² | Verblendung | WA-HS | Zimmer- und Holzbauarbeiten
 | H2 Ebene +1 | 1155Veb2005797417 | m² | Verblendung | WA-HS | Zimmer- und Holzbauarbeiten
 | H2 Ebene +1 | 1155Veb2005786159 | m² | Verblendung | WA-HS | Zimmer- und Holzbauarbeiten
 | H2 Ebene +1 | 1155Veb2005786075 | m² | Verblendung | WA-HS | Zimmer- und Holzbauarbeiten
 | H2 Ebene +1 | 1155Veb2005786243 | m² | Verblendung | WA-HS | Zimmer- und Holzbauarbeiten
 | H2 Ebene +1 | 1155Veb2005806526 | m² | Verblendung | WA-HS | Zimmer- und Holzbauarbeiten
 | H2 Ebene +1 | 1155Veb2005806048 | m² | Verblendung | WA-HS | Zimmer- und Holzbauarbeiten
 | H2 Ebene +1 | 1155Veb2005805621 | m² | Verblendung | WA-HS | Zimmer- und Holzbauarbeiten
 | H2 Ebene +1 | 1155Veb2005805368 | m² | Verblendung | WA-HS | Zimmer- und Holzbauarbeiten
 | H2 Ebene +1 | 1155Veb2005804959 | m² | Verblendung | WA-HS | Zimmer- und Holzbauarbeiten
 | H2 Ebene +1 | 1155Veb2005808103 | m² | Verblendung | WA-HS | Zimmer- und Holzbauarbeiten
 | H2 Ebene +1 | 1155Veb2005822810 | m² | Verblendung | WA-HS | Zimmer- und Holzbauarbeiten
 | H2 Ebene +1 | 1155Veb2005776458 | m² | Verblendung | WA-HS | Zimmer- und Holzbauarbeiten
 | H2 Ebene +1 | 1155Veb2005776612 | m² | Verblendung | WA-HS | Zimmer- und Holzbauarbeiten
 | H2 Ebene +1 | 1155Veb2005776721 | m² | Verblendung | WA-HS | Zimmer- und Holzbauarbeiten
 | H2 Ebene +1 | 1155Veb2005820825 | m² | Verblendung | WA-HS | Zimmer- und Holzbauarbeiten
 | H2 Ebene +1 | 1155Veb2005776957 | m² | Verblendung | WA-HS | Zimmer- und Holzbauarbeiten
 | H2 Ebene +1 | 1155Veb2005777061 | m² | Verblendung | WA-HS | Zimmer- und Holzbauarbeiten
 | H2 Ebene +1 | 1155Veb2005777163 | m² | Verblendung | WA-HS | Zimmer- und Holzbauarbeiten
 | H2 Ebene +1 | 1155Veb2005797173 | m² | Verblendung | WA-HS | Zimmer- und Holzbauarbeiten
 | H2 Ebene +1 | 1155Veb2005779220 | m² | Verblendung | WA-HS | Zimmer- und Holzbauarbeiten
 | H2 Ebene +1 | 1155Veb2005785518 | m² | Verblendung | WA-HS | Zimmer- und Holzbauarbeiten
 | H2 Ebene +1 | 1155Veb2005785049 | m² | Verblendung | WA-HS | Zimmer- und Holzbauarbeiten
 | H2 Ebene +1 | 1155Veb2005797906 | m² | Verblendung | WA-HS | Zimmer- und Holzbauarbeiten
 | H2 Ebene +1 | 1155Veb2005798232 | m² | Verblendung | WA-HS | Zimmer- und Holzbauarbeiten
 | H2 Ebene +1 | 1155Veb2005798321 | m² | Verblendung | WA-HS | Zimmer- und Holzbauarbeiten
 | H2 Ebene +1 | 1155Veb2005798410 | m² | Verblendung | WA-HS | Zimmer- und Holzbauarbeiten
 | H2 Ebene +1 | 1155Veb2005798499 | m² | Verblendung | WA-HS | Zimmer- und Holzbauarbeiten
 | H2 Ebene +1 | 1155Veb2005803650 | m² | Verblendung | WA-HS | Zimmer- und Holzbauarbeiten
 | H2 Ebene +1 | 1155Veb2005803463 | m² | Verblendung | WA-HS | Zimmer- und Holzbauarbeiten
 | H2 Ebene +1 | 1155Veb2005803277 | m² | Verblendung | WA-HS | Zimmer- und Holzbauarbeiten
 | H2 Ebene +1 | 1155Veb2005803100 | m² | Verblendung | WA-HS | Zimmer- und Holzbauarbeiten
 | H2 Ebene +1 | 1155Veb2005802183 | m² | Verblendung | WA-HS | Zimmer- und Holzbauarbeiten
 | H2 Ebene +1 | 1155Veb2005800305 | m² | Verblendung | WA-HS | Zimmer- und Holzbauarbeiten
 | H2 Ebene +1 | 1155Veb2005800501 | m² | Verblendung | WA-HS | Zimmer- und Holzbauarbeiten
 | H2 Ebene +1 | 1155Veb2005800610 | m² | Verblendung | WA-HS | Zimmer- und Holzbauarbeiten
 | H2 Ebene +1 | 1155Veb2005800196 | m² | Verblendung | WA-HS | Zimmer- und Holzbauarbeiten
 | H2 Ebene +1 | 1155Veb2005804335 | m² | Verblendung | WA-HS | Zimmer- und Holzbauarbeiten
 | H2 Ebene +1 | 1155Veb2005804025 | m² | Verblendung | WA-HS | Zimmer- und Holzbauarbeiten
 | H2 Ebene +1 | 1155Veb2005804129 | m² | Verblendung | WA-HS | Zimmer- und Holzbauarbeiten
 | H2 Ebene +1 | 1155Veb2005804233 | m² | Verblendung | WA-HS | Zimmer- und Holzbauarbeiten
8 x  | H2 Ebene +1
 | H2 Ebene 0 | 1105Veb2005790918 | m² | Verblendung | WA-HS | Zimmer- und Holzbauarbeiten
 | H2 Ebene 0 | 1105Veb2005791144 | m² | Verblendung | WA-HS | Zimmer- und Holzbauarbeiten
 | H2 Ebene 0 | 1105Veb2005791334 | m² | Verblendung | WA-HS | Zimmer- und Holzbauarbeiten
 | H2 Ebene 0 | 1105Veb2005791770 | m² | Verblendung | WA-HS | Zimmer- und Holzbauarbeiten
 | H2 Ebene 0 | 1105Veb2005791979 | m² | Verblendung | WA-HS | Zimmer- und Holzbauarbeiten
 | H2 Ebene 0 | 1105Veb2005791531 | m² | Verblendung | WA-HS | Zimmer- und Holzbauarbeiten
 | H2 Ebene 0 | 1105Veb2005792976 | m² | Verblendung | WA-HS | Zimmer- und Holzbauarbeiten
 | H2 Ebene 0 | 1105Veb2005793090 | m² | Verblendung | WA-HS | Zimmer- und Holzbauarbeiten
 | H2 Ebene 0 | 1105Veb2005793172 | m² | Verblendung | WA-HS | Zimmer- und Holzbauarbeiten
 | H2 Ebene 0 | 1105Veb2005793266 | m² | Verblendung | WA-HS | Zimmer- und Holzbauarbeiten
 | H2 Ebene 0 | 1105Veb2005793348 | m² | Verblendung | WA-HS | Zimmer- und Holzbauarbeiten
 | H2 Ebene 0 | 1105Veb2005780490 | m² | Verblendung | WA-HS | Zimmer- und Holzbauarbeiten
 | H2 Ebene 0 | 1105Veb2005778665 | m² | Verblendung | WA-HS | Zimmer- und Holzbauarbeiten
 | H2 Ebene 0 | 1105Veb2005778042 | m² | Verblendung | WA-HS | Zimmer- und Holzbauarbeiten
 | H2 Ebene 0 | 1105Veb2005777386 | m² | Verblendung | WA-HS | Zimmer- und Holzbauarbeiten
 | H2 Ebene 0 | 1105Veb2005777666 | m² | Verblendung | WA-HS | Zimmer- und Holzbauarbeiten
 | H2 Ebene 0 | 1105Veb2005778920 | m² | Verblendung | WA-HS | Zimmer- und Holzbauarbeiten
 | H2 Ebene 0 | 1105Veb2005778322 | m² | Verblendung | WA-HS | Zimmer- und Holzbauarbeiten
 | H2 Ebene 0 | 1105Veb2005780294 | m² | Verblendung | WA-HS | Zimmer- und Holzbauarbeiten
 | H2 Ebene 0 | 1105Veb2005780376 | m² | Verblendung | WA-HS | Zimmer- und Holzbauarbeiten
 | H2 Ebene 0 | 1105Veb2005779986 | m² | Verblendung | WA-HS | Zimmer- und Holzbauarbeiten
 | H2 Ebene 0 | 1105Veb2005780184 | m² | Verblendung | WA-HS | Zimmer- und Holzbauarbeiten
 | H2 Ebene 0 | 1105Veb2005789663 | m² | Verblendung | WA-HS | Zimmer- und Holzbauarbeiten
 | H2 Ebene 0 | 1105Veb2005790440 | m² | Verblendung | WA-HS | Zimmer- und Holzbauarbeiten
 | H2 Ebene 0 | 1105Veb2005789170 | m² | Verblendung | WA-HS | Zimmer- und Holzbauarbeiten
 | H2 Ebene 0 | 1105Veb2005779315 | m² | Verblendung | WA-HS | Zimmer- und Holzbauarbeiten
 | H2 Ebene 0 | 1105Veb2005779397 | m² | Verblendung | WA-HS | Zimmer- und Holzbauarbeiten
 | H2 Ebene 0 | 1105Veb2005779479 | m² | Verblendung | WA-HS | Zimmer- und Holzbauarbeiten
 | H2 Ebene 0 | 1105Veb2005793484 | m² | Verblendung | WA-HS | Zimmer- und Holzbauarbeiten
 | H2 Ebene 0 | 1105Veb2005793566 | m² | Verblendung | WA-HS | Zimmer- und Holzbauarbeiten
 | H2 Ebene 0 | 1105Veb2005793648 | m² | Verblendung | WA-HS | Zimmer- und Holzbauarbeiten
 | H2 Ebene 0 | 1105Veb2005792521 | m² | Verblendung | WA-HS | Zimmer- und Holzbauarbeiten
 | H2 Ebene 0 | 1105Veb2005792613 | m² | Verblendung | WA-HS | Zimmer- und Holzbauarbeiten
 | H2 Ebene 0 | 1105Veb2005792695 | m² | Verblendung | WA-HS | Zimmer- und Holzbauarbeiten
 | H2 Ebene 0 | 1105Veb2005775099 | m² | Verblendung | WA-HS | Zimmer- und Holzbauarbeiten
 | H2 Ebene 0 | 1105Veb2005774664 | m² | Verblendung | WA-HS | Zimmer- und Holzbauarbeiten
 | H2 Ebene 0 | 1105Veb2005775886 | m² | Verblendung | WA-HS | Zimmer- und Holzbauarbeiten
 | H2 Ebene 0 | 1105Veb2005775462 | m² | Verblendung | WA-HS | Zimmer- und Holzbauarbeiten
 | H2 Ebene 0 | 1105Veb2005775279 | m² | Verblendung | WA-HS | Zimmer- und Holzbauarbeiten
 | H2 Ebene 0 | 1105Veb2005780574 | m² | Verblendung | WA-HS | Zimmer- und Holzbauarbeiten
 | H2 Ebene 0 | 1105Veb2005785676 | m² | Verblendung | WA-HS | Zimmer- und Holzbauarbeiten
 | H2 Ebene 0 | 1105Veb2005785451 | m² | Verblendung | WA-HS | Zimmer- und Holzbauarbeiten
 | H2 Ebene 0 | 1105Veb2005785369 | m² | Verblendung | WA-HS | Zimmer- und Holzbauarbeiten
 | H2 Ebene 0 | 1105Veb2005785209 | m² | Verblendung | WA-HS | Zimmer- und Holzbauarbeiten
 | H2 Ebene 0 | 1105Veb2005780729 | m² | Verblendung | WA-HS | Zimmer- und Holzbauarbeiten
 | H2 Ebene 0 | 1105Veb2005790439 | m² | Verblendung | WA-HS | Zimmer- und Holzbauarbeiten
 | H2 Ebene 0 | 1105Veb2005785779 | m² | Verblendung | WA-HS | Zimmer- und Holzbauarbeiten
 | H2 Ebene 0 | 1105Veb2005776708 | m² | Verblendung | WA-HS | Zimmer- und Holzbauarbeiten
 | H2 Ebene 0 | 1105Veb2005776870 | m² | Verblendung | WA-HS | Zimmer- und Holzbauarbeiten
 | H2 Ebene 0 | 1105Veb2005776987 | m² | Verblendung | WA-HS | Zimmer- und Holzbauarbeiten
8 x  | H2 Ebene 0

# IfcColumn (112)
PredefinedType: COLUMN
AllplanAttributes - 2D Interaktion: yes; Abrechnungsart: m; Objektname: Stütze
Pset_ColumnCommon - Status: NEW; LoadBearing: yes
Name | In | Material = AllplanAttributes, Material | Codetext = Reference | Gewerk | OKFF | Positionsnummer_Text | Allright_Bauteil_ID | IsExternal | FireRating | ThermalTransmittance (W/K/m2) | Material Statik
 | H2 Ebene +4/ Dachebene | ST-H | Codetext | Zimmer- und Holzbauarbeiten | 14.5 | S2 | 1406St 0000003533 | no | REI 60-A1 - D,s2-d0 /A1 | 0 | AllplanAttributes - Ortscode_Geschoßbezeichnung: E04
 | H2 Ebene +4/ Dachebene | ST-H | Codetext | Zimmer- und Holzbauarbeiten | 14.5 | S11 | 1406St 0000004784 | no | REI 60-A1 - D,s2-d0 /A1 | 0 | Baubuche GL75
 | H2 Ebene +3 | ST-H | Codetext | Zimmer- und Holzbauarbeiten | 11.25 | PF9 | 1263St 0812661720 | no | REI 60-A1 - D,s2-d0 /A1 | 0 | AllplanAttributes - Ortscode_Geschoßbezeichnung: E03
 | H2 Ebene +3 | ST-H | Codetext | Zimmer- und Holzbauarbeiten | 11.25 | PF9 | 1263St 0812661708 | no | REI 60-A1 - D,s2-d0 /A1 | 0 | AllplanAttributes - Ortscode_Geschoßbezeichnung: E03
 | H2 Ebene +3 | ST-H | Codetext | Zimmer- und Holzbauarbeiten | 11.25 | PF9 | 1263St 0812661702 | no | REI 60-A1 - D,s2-d0 /A1 | 0 | AllplanAttributes - Ortscode_Geschoßbezeichnung: E03
 | H2 Ebene +3 | ST-H | Codetext | Zimmer- und Holzbauarbeiten | 11.25 | PF9 | 1263St 0813030780 | no | REI 60-A1 - D,s2-d0 /A1 | 0
 | H2 Ebene +3 | ST-H | Codetext | Zimmer- und Holzbauarbeiten | 11.25 | PF9 | 1263St 0812661726 | no | REI 60-A1 - D,s2-d0 /A1 | 0 | AllplanAttributes - Ortscode_Geschoßbezeichnung: E03
 | H2 Ebene +3 | ST-H | Codetext | Zimmer- und Holzbauarbeiten | 11.25 | PF9 | 1263St 0812661723 | no | REI 60-A1 - D,s2-d0 /A1 | 0 | AllplanAttributes - Ortscode_Geschoßbezeichnung: E03
 | H2 Ebene +3 | ST-H | Codetext | Zimmer- und Holzbauarbeiten | 11.25 | PF9 | 1263St 0812661729 | no | REI 60-A1 - D,s2-d0 /A1 | 0 | AllplanAttributes - Ortscode_Geschoßbezeichnung: E03
 | H2 Ebene +3 | ST-H | Codetext | Zimmer- und Holzbauarbeiten | 11.25 | PF9 | 1263St 0812661732 | no | REI 60-A1 - D,s2-d0 /A1 | 0 | AllplanAttributes - Ortscode_Geschoßbezeichnung: E03
 | H2 Ebene +3 | ST-H | Codetext | Zimmer- und Holzbauarbeiten | 11.25 | PF9 | 1263St 0813030706 | no | REI 60-A1 - D,s2-d0 /A1 | 0
 | H2 Ebene +3 | ST-H | Codetext | Zimmer- und Holzbauarbeiten | 11.25 | PF9 | 1263St 0813030743 | no | REI 60-A1 - D,s2-d0 /A1 | 0
 | H2 Ebene +3 | ST-H | Codetext | Zimmer- und Holzbauarbeiten | 11.25 | PF9 | 1263St 0812661699 | no | REI 60-A1 - D,s2-d0 /A1 | 0 | AllplanAttributes - Ortscode_Geschoßbezeichnung: E03
 | H2 Ebene +3 | ST-H | Codetext | Zimmer- und Holzbauarbeiten | 11.25 | PF9 | 1263St 0812661705 | no | REI 60-A1 - D,s2-d0 /A1 | 0 | AllplanAttributes - Ortscode_Geschoßbezeichnung: E03
 | H2 Ebene +3 | ST-H | Codetext | Zimmer- und Holzbauarbeiten | 11.25 | PF9 | 1263St 0813034870 | no | REI 60-A1 - D,s2-d0 /A1 | 0
 | H2 Ebene +3 | ST-H | Codetext | Zimmer- und Holzbauarbeiten | 11.25 | PF9 | 1263St 0813034862 | no | REI 60-A1 - D,s2-d0 /A1 | 0
 | H2 Ebene +3 | ST-H | Codetext | Zimmer- und Holzbauarbeiten | 11.25 | PF9 | 1263St 0813034854 | no | REI 60-A1 - D,s2-d0 /A1 | 0
 | H2 Ebene +3 | ST-H | Codetext | Zimmer- und Holzbauarbeiten | 11.25 | PF9 | 1263St 0813034836 | no | REI 60-A1 - D,s2-d0 /A1 | 0
 | H2 Ebene +3 | ST-H | Codetext | Zimmer- und Holzbauarbeiten | 11.25 | PF9 | 1263St 0812775322 | no | REI 60-A1 - D,s2-d0 /A1 | 0 | AllplanAttributes - Ortscode_Geschoßbezeichnung: E03
 | H2 Ebene +3 | ST-H | Codetext | Zimmer- und Holzbauarbeiten | 11.25 | PF9 | 1263St 0812775325 | no | REI 60-A1 - D,s2-d0 /A1 | 0 | AllplanAttributes - Ortscode_Geschoßbezeichnung: E03
 | H2 Ebene +3 | ST-H | Codetext | Zimmer- und Holzbauarbeiten | 11.25 | PF9 | 1263St 0812661717 | no | REI 60-A1 - D,s2-d0 /A1 | 0 | AllplanAttributes - Ortscode_Geschoßbezeichnung: E03
 | H2 Ebene +3 | ST-H | Codetext | Zimmer- und Holzbauarbeiten | 11.25 | PF9 | 1263St 0813030525 | no | REI 60-A1 - D,s2-d0 /A1 | 0
 | H2 Ebene +3 | ST-H | Codetext | Zimmer- und Holzbauarbeiten | 11.25 | PF9 | 1263St 0812775369 | no | REI 60-A1 - D,s2-d0 /A1 | 0 | AllplanAttributes - Ortscode_Geschoßbezeichnung: E03
 | H2 Ebene +3 | ST-H | Codetext | Zimmer- und Holzbauarbeiten | 11.25 | PF9 | 1263St 0812661714 | no | REI 60-A1 - D,s2-d0 /A1 | 0 | AllplanAttributes - Ortscode_Geschoßbezeichnung: E03
 | H2 Ebene +3 | ST-H | Codetext | Zimmer- und Holzbauarbeiten | 11.25 | PF9 | 1263St 0812775342 | no | REI 60-A1 - D,s2-d0 /A1 | 0 | AllplanAttributes - Ortscode_Geschoßbezeichnung: E03
 | H2 Ebene +3 | ST-H | Codetext | Zimmer- und Holzbauarbeiten | 11.25 | PF9 | 1263St 0812661711 | no | REI 60-A1 - D,s2-d0 /A1 | 0 | AllplanAttributes - Ortscode_Geschoßbezeichnung: E03
 | H2 Ebene +3 | ST-H | Codetext | Zimmer- und Holzbauarbeiten | 11.25 | S11 | 1263St 0812954137 | no | REI 60-A1 - D,s2-d0 /A1 | 0 | Baubuche GL75
 | H2 Ebene +2 | H | Codetext | Zimmer- und Holzbauarbeiten | 7.5 |  | 1205St 0000310792 | no | 0 | 0.9 | FSH Baubuche GL75 | AllplanAttributes - Schallschutzklasse: 32; Sicherheitsklasse: -; ash D_Detailverweis: <undefiniert>; Sonnenschutztyp: Movable; g-Wert: 0,51
 | H2 Ebene +2 | H | Codetext | Zimmer- und Holzbauarbeiten | 7.5 |  | 1205St 0000001241 | no | 0 | 0.9 | FSH Baubuche GL75 | AllplanAttributes - Schallschutzklasse: 32; Sicherheitsklasse: -; ash D_Detailverweis: <undefiniert>; Sonnenschutztyp: Movable; g-Wert: 0,51
 | H2 Ebene +2 | H | Codetext | Zimmer- und Holzbauarbeiten | 7.5 |  | 1205St 0000001810 | no | 0 | 0.9 | BSH GL24c | AllplanAttributes - Schallschutzklasse: 32; Sicherheitsklasse: -; ash D_Detailverweis: <undefiniert>; Sonnenschutztyp: Movable; g-Wert: 0,51
 | H2 Ebene +2 | H | Codetext | Zimmer- und Holzbauarbeiten | 7.5 |  | 1205St 0000247261 | no | 0 | 0.9 | FSH Baubuche GL75 | AllplanAttributes - Schallschutzklasse: 32; Sicherheitsklasse: -; ash D_Detailverweis: <undefiniert>; Sonnenschutztyp: Movable; g-Wert: 0,51
QRO 140x5 | H2 Ebene +2 | QRO |  | Stahlbauarbeiten | 7.5 |  | 1213St 0812969952 | yes | REI 90-A1 | 0 | AllplanAttributes - Ortscode_Geschoßbezeichnung: E02; Dateiname: C:\ProgramData\Nemetschek\Allplan\2024\Etc\Library\Engineering\Steel sections\2D profiles angular idealiz\Hollow square cold finished\140 x 140 x 5.sym; Folgenname: 140 x 140 x 5; Bezeichnung: QRO 140x5
QRO 140x5 | H2 Ebene +2 | QRO |  | Stahlbauarbeiten | 7.5 |  | 1213St 0812969928 | yes | REI 90-A1 | 0 | AllplanAttributes - Ortscode_Geschoßbezeichnung: E02; Dateiname: C:\ProgramData\Nemetschek\Allplan\2024\Etc\Library\Engineering\Steel sections\2D profiles angular idealiz\Hollow square cold finished\140 x 140 x 5.sym; Folgenname: 140 x 140 x 5; Bezeichnung: QRO 140x5
 | H2 Ebene +2 | H | Codetext | Zimmer- und Holzbauarbeiten | 7.5 |  | 1213St 0813456838 | no | REI 60-A1 - A2,s1-d0 | 0 | NH C24 | AllplanAttributes - Ortscode_Geschoßbezeichnung: E02
 | H2 Ebene +2 | H | Codetext | Zimmer- und Holzbauarbeiten | 7.5 |  | 1213St 0813456771 | no | REI 60-A1 - A2,s1-d0 | 0 | NH C24 | AllplanAttributes - Ortscode_Geschoßbezeichnung: E02
 | H2 Ebene +2 | H | Codetext | Zimmer- und Holzbauarbeiten | 7.5 |  | 1213St 0813458278 | no | REI 60-A1 - A2,s1-d0 | 0 | NH C24 | AllplanAttributes - Ortscode_Geschoßbezeichnung: E02
 | H2 Ebene +2 | H | Codetext | Zimmer- und Holzbauarbeiten | 7.5 |  | 1213St 0813458775 | no | REI 60-A1 - A2,s1-d0 | 0 | NH C24 | AllplanAttributes - Ortscode_Geschoßbezeichnung: E02
QRO 140x5 | H2 Ebene +2 | QRO |  | Stahlbauarbeiten | 7.5 |  | 1213St 0812970104 | yes | REI 90-A1 | 0 | AllplanAttributes - Ortscode_Geschoßbezeichnung: E02; Dateiname: C:\ProgramData\Nemetschek\Allplan\2024\Etc\Library\Engineering\Steel sections\2D profiles angular idealiz\Hollow square cold finished\140 x 140 x 5.sym; Folgenname: 140 x 140 x 5; Bezeichnung: QRO 140x5
QRO 140x5 | H2 Ebene +2 | QRO |  | Stahlbauarbeiten | 7.5 |  | 1213St 0812970094 | yes | REI 90-A1 | 0 | AllplanAttributes - Ortscode_Geschoßbezeichnung: E02; Dateiname: C:\ProgramData\Nemetschek\Allplan\2024\Etc\Library\Engineering\Steel sections\2D profiles angular idealiz\Hollow square cold finished\140 x 140 x 5.sym; Folgenname: 140 x 140 x 5; Bezeichnung: QRO 140x5
QRO 140x5 | H2 Ebene +2 | QRO |  | Stahlbauarbeiten | 7.5 |  | 1213St 0812970096 | yes | REI 90-A1 | 0 | AllplanAttributes - Ortscode_Geschoßbezeichnung: E02; Dateiname: C:\ProgramData\Nemetschek\Allplan\2024\Etc\Library\Engineering\Steel sections\2D profiles angular idealiz\Hollow square cold finished\140 x 140 x 5.sym; Folgenname: 140 x 140 x 5; Bezeichnung: QRO 140x5
QRO 140x5 | H2 Ebene +2 | QRO |  | Stahlbauarbeiten | 7.5 |  | 1213St 0812970098 | yes | REI 90-A1 | 0 | AllplanAttributes - Ortscode_Geschoßbezeichnung: E02; Dateiname: C:\ProgramData\Nemetschek\Allplan\2024\Etc\Library\Engineering\Steel sections\2D profiles angular idealiz\Hollow square cold finished\140 x 140 x 5.sym; Folgenname: 140 x 140 x 5; Bezeichnung: QRO 140x5
 | H2 Ebene +2 | H | Codetext | Zimmer- und Holzbauarbeiten | 7.5 | U100 | 1213St 0813506008 | no | REI 60-A1 - A2,s1-d0 | 0 | FSH Baubuche GL75 | AllplanAttributes - Ortscode_Geschoßbezeichnung: E02; Sicherheitsklasse: -
 | H2 Ebene +2 | H | Codetext | Zimmer- und Holzbauarbeiten | 7.5 | U100 | 1213St 0813505977 | no | REI 60-A1 - A2,s1-d0 | 0 | FSH Baubuche GL75 | AllplanAttributes - Ortscode_Geschoßbezeichnung: E02; Sicherheitsklasse: -
QRO 140x5 | H2 Ebene +2 | QRO |  | Stahlbauarbeiten | 7.5 |  | 1213St 0812970100 | yes | REI 90-A1 | 0 | AllplanAttributes - Ortscode_Geschoßbezeichnung: E02; Dateiname: C:\ProgramData\Nemetschek\Allplan\2024\Etc\Library\Engineering\Steel sections\2D profiles angular idealiz\Hollow square cold finished\140 x 140 x 5.sym; Folgenname: 140 x 140 x 5; Bezeichnung: QRO 140x5
 | H2 Ebene +2 | H | Codetext | Zimmer- und Holzbauarbeiten | 7.5 |  | 1213St 0812970056 | no | REI 60-A1 - A2,s1-d0 | 0 | BSH GL24c | AllplanAttributes - Ortscode_Geschoßbezeichnung: E02
 | H2 Ebene +2 | H | Codetext | Zimmer- und Holzbauarbeiten | 7.5 |  | 1213St 0812969895 | no | REI 60-A1 - A2,s1-d0 | 0 | BSH GL24c | AllplanAttributes - Ortscode_Geschoßbezeichnung: E02
 | H2 Ebene +2 | H | Codetext | Zimmer- und Holzbauarbeiten | 7.5 |  | 1213St 0812970146 | no | REI 60-A1 - A2,s1-d0 | 0 | BSH GL24c | AllplanAttributes - Ortscode_Geschoßbezeichnung: E02; Schallschutzklasse: 52
 | H2 Ebene +2 | H | Codetext | Zimmer- und Holzbauarbeiten | 7.5 |  | 1213St 0812970041 | no | REI 60-A1 - A2,s1-d0 | 0 | BSH GL24c | AllplanAttributes - Ortscode_Geschoßbezeichnung: E02; Schallschutzklasse: 52
 | H2 Ebene +2 | H | Codetext | Zimmer- und Holzbauarbeiten | 7.5 |  | 1213St 0812970112 | no | REI 60-A1 - A2,s1-d0 | 0 | FSH Baubuche GL75 | AllplanAttributes - Ortscode_Geschoßbezeichnung: E02
 | H2 Ebene +2 | H | Codetext | Zimmer- und Holzbauarbeiten | 7.5 |  | 1213St 0812970116 | no | REI 60-A1 - A2,s1-d0 | 0 | BSH GL24c | AllplanAttributes - Ortscode_Geschoßbezeichnung: E02
 | H2 Ebene +2 | H | Codetext | Zimmer- und Holzbauarbeiten | 7.5 |  | 1213St 0812970089 | no | REI 60-A1 - A2,s1-d0 | 0 | BSH GL24c | AllplanAttributes - Ortscode_Geschoßbezeichnung: E02
 | H2 Ebene +2 | H | Codetext | Zimmer- und Holzbauarbeiten | 7.5 |  | 1213St 0812970077 | no | REI 60-A1 - A2,s1-d0 | 0 | BSH GL24c | AllplanAttributes - Ortscode_Geschoßbezeichnung: E02
 | H2 Ebene +2 | H | Codetext | Zimmer- und Holzbauarbeiten | 7.5 |  | 1213St 0812970069 | no | REI 60-A1 - A2,s1-d0 | 0 | BSH GL24c | AllplanAttributes - Ortscode_Geschoßbezeichnung: E02
 | H2 Ebene +2 | H | Codetext | Zimmer- und Holzbauarbeiten | 7.5 |  | 1213St 0812970130 | no | REI 60-A1 - A2,s1-d0 | 0 | BSH GL24c | AllplanAttributes - Ortscode_Geschoßbezeichnung: E02
QRO 140x5 | H2 Ebene +2 | QRO |  | Stahlbauarbeiten | 7.5 |  | 1213St 0812970102 | yes | REI 90-A1 | 0 | AllplanAttributes - Ortscode_Geschoßbezeichnung: E02; Dateiname: C:\ProgramData\Nemetschek\Allplan\2024\Etc\Library\Engineering\Steel sections\2D profiles angular idealiz\Hollow square cold finished\140 x 140 x 5.sym; Folgenname: 140 x 140 x 5; Bezeichnung: QRO 140x5
 | H2 Ebene +1 | H | Codetext | Zimmer- und Holzbauarbeiten | 3.75 | U23 | 1155St 0000001241 | no | 0 | 0.9 | FSH Baubuche GL75 | AllplanAttributes - Schallschutzklasse: 32; Sicherheitsklasse: -; Sonnenschutztyp: Movable; g-Wert: 0,51
 | H2 Ebene +1 | H | Codetext | Zimmer- und Holzbauarbeiten | 3.75 | U23 | 1155St 0813773489 | no | 0 | 0 | FSH Baubuche GL75 | AllplanAttributes - Sicherheitsklasse: -
 | H2 Ebene +1 | H | Codetext | Zimmer- und Holzbauarbeiten | 3.75 | U23 | 1155St 0813754091 | no | 0 | 0 | FSH Baubuche GL75 | AllplanAttributes - Sicherheitsklasse: -
 | H2 Ebene +1 | H | Codetext | Zimmer- und Holzbauarbeiten | 3.75 | U23 | 1155St 0813760479 | no | 0 | 0.9 | FSH Baubuche GL75 | AllplanAttributes - Schallschutzklasse: 32; Sicherheitsklasse: -; Sonnenschutztyp: Movable; g-Wert: 0,51
QRO 140x5 | H2 Ebene +1 | QRO |  | Stahlbauarbeiten | 3.75 | S46 | 1163St 0812747144 | yes | REI 90-A1 | 0 | AllplanAttributes - Ortscode_Geschoßbezeichnung: E01; Dateiname: C:\ProgramData\Nemetschek\Allplan\2024\Etc\Library\Engineering\Steel sections\2D profiles angular idealiz\Hollow square cold finished\140 x 140 x 5.sym; Folgenname: 140 x 140 x 5; Bezeichnung: QRO 140x5
QRO 140x5 | H2 Ebene +1 | QRO |  | Stahlbauarbeiten | 3.75 | S46 | 1163St 0812747137 | yes | REI 90-A1 | 0 | AllplanAttributes - Ortscode_Geschoßbezeichnung: E01; Dateiname: C:\ProgramData\Nemetschek\Allplan\2024\Etc\Library\Engineering\Steel sections\2D profiles angular idealiz\Hollow square cold finished\140 x 140 x 5.sym; Folgenname: 140 x 140 x 5; Bezeichnung: QRO 140x5
QRO 140x5 | H2 Ebene +1 | QRO |  | Stahlbauarbeiten | 3.75 | S49 | 1163St 0812747170 | yes | REI 90-A1 | 0 | AllplanAttributes - Ortscode_Geschoßbezeichnung: E01; Dateiname: C:\ProgramData\Nemetschek\Allplan\2024\Etc\Library\Engineering\Steel sections\2D profiles angular idealiz\Hollow square cold finished\140 x 140 x 5.sym; Folgenname: 140 x 140 x 5; Bezeichnung: QRO 140x5
QRO 140x5 | H2 Ebene +1 | QRO |  | Stahlbauarbeiten | 3.75 | S50 | 1163St 0812747203 | yes | REI 90-A1 | 0 | AllplanAttributes - Ortscode_Geschoßbezeichnung: E01; Dateiname: C:\ProgramData\Nemetschek\Allplan\2024\Etc\Library\Engineering\Steel sections\2D profiles angular idealiz\Hollow square cold finished\140 x 140 x 5.sym; Folgenname: 140 x 140 x 5; Bezeichnung: QRO 140x5
QRO 140x5 | H2 Ebene +1 | QRO |  | Stahlbauarbeiten | 3.75 | S47 | 1163St 0812747251 | yes | REI 90-A1 | 0 | AllplanAttributes - Ortscode_Geschoßbezeichnung: E01; Dateiname: C:\ProgramData\Nemetschek\Allplan\2024\Etc\Library\Engineering\Steel sections\2D profiles angular idealiz\Hollow square cold finished\140 x 140 x 5.sym; Folgenname: 140 x 140 x 5; Bezeichnung: QRO 140x5
QRO 140x5 | H2 Ebene +1 | QRO |  | Stahlbauarbeiten | 3.75 | S51 | 1163St 0812747238 | yes | REI 90-A1 | 0 | AllplanAttributes - Ortscode_Geschoßbezeichnung: E01; Dateiname: C:\ProgramData\Nemetschek\Allplan\2024\Etc\Library\Engineering\Steel sections\2D profiles angular idealiz\Hollow square cold finished\140 x 140 x 5.sym; Folgenname: 140 x 140 x 5; Bezeichnung: QRO 140x5
QRO 140x5 | H2 Ebene +1 | QRO |  | Stahlbauarbeiten | 3.75 | S49 | 1163St 0812747180 | yes | REI 90-A1 | 0 | AllplanAttributes - Ortscode_Geschoßbezeichnung: E01; Dateiname: C:\ProgramData\Nemetschek\Allplan\2024\Etc\Library\Engineering\Steel sections\2D profiles angular idealiz\Hollow square cold finished\140 x 140 x 5.sym; Folgenname: 140 x 140 x 5; Bezeichnung: QRO 140x5
QRO 140x5 | H2 Ebene +1 | QRO |  | Stahlbauarbeiten | 3.75 | S50 | 1163St 0812747252 | yes | REI 90-A1 | 0 | AllplanAttributes - Ortscode_Geschoßbezeichnung: E01; Dateiname: C:\ProgramData\Nemetschek\Allplan\2024\Etc\Library\Engineering\Steel sections\2D profiles angular idealiz\Hollow square cold finished\140 x 140 x 5.sym; Folgenname: 140 x 140 x 5; Bezeichnung: QRO 140x5
 | H2 Ebene +1 | H | Codetext | Zimmer- und Holzbauarbeiten | 3.75 | S43 | 1163St 0814386243 | no | REI 60-A1 - A2,s1-d0 | 0 | NH C24
 | H2 Ebene +1 | H | Codetext | Zimmer- und Holzbauarbeiten | 3.75 | S43 | 1163St 0814386272 | no | REI 60-A1 - A2,s1-d0 | 0 | NH C24
 | H2 Ebene +1 | H | Codetext | Zimmer- und Holzbauarbeiten | 3.75 | S43 | 1163St 0814370890 | no | REI 60-A1 - A2,s1-d0 | 0 | NH C24
 | H2 Ebene +1 | H | Codetext | Zimmer- und Holzbauarbeiten | 3.75 | S43 | 1163St 0814370809 | no | REI 60-A1 - A2,s1-d0 | 0 | NH C24
 | H2 Ebene +1 | H | Codetext | Zimmer- und Holzbauarbeiten | 3.75 | U100 | 1163St 0814149579 | no | REI 60-A1 - A2,s1-d0 | 0 | FSH Baubuche GL75 | AllplanAttributes - Sicherheitsklasse: -
 | H2 Ebene +1 | H | Codetext | Zimmer- und Holzbauarbeiten | 3.75 | U100 | 1163St 0814149596 | no | REI 60-A1 - A2,s1-d0 | 0 | FSH Baubuche GL75 | AllplanAttributes - Sicherheitsklasse: -
 | H2 Ebene +1 | H | Codetext | Zimmer- und Holzbauarbeiten | 3.75 | S45 | 1163St 0812442474 | no | REI 60-A1 - A2,s1-d0 | 0 | BSH GL24c
 | H2 Ebene +1 | H | Codetext | Zimmer- und Holzbauarbeiten | 3.75 | S44 | 1163St 0812447437 | no | REI 60-A1 - A2,s1-d0 | 0 | BSH GL24c
 | H2 Ebene +1 | H | Codetext | Zimmer- und Holzbauarbeiten | 3.75 | S43 | 1163St 0812442477 | no | REI 60-A1 - A2,s1-d0 | 0 | BSH GL24c
 | H2 Ebene +1 | H | Codetext | Zimmer- und Holzbauarbeiten | 3.75 | S43 | 1163St 0812523684 | no | REI 60-A1 - A2,s1-d0 | 0 | BSH GL24c
 | H2 Ebene +1 | H | Codetext | Zimmer- und Holzbauarbeiten | 3.75 | S45 | 1163St 0812523683 | no | REI 60-A1 - A2,s1-d0 | 0 | BSH GL24c
 | H2 Ebene +1 | H | Codetext | Zimmer- und Holzbauarbeiten | 3.75 | U100 | 1163St 0812523681 | no | REI 60-A1 - A2,s1-d0 | 0 | FSH Baubuche GL75
 | H2 Ebene +1 | H | Codetext | Zimmer- und Holzbauarbeiten | 3.75 | S42 | 1163St 0812523686 | no | REI 60-A1 - A2,s1-d0 | 0 | BSH GL24c
 | H2 Ebene +1 | H | Codetext | Zimmer- und Holzbauarbeiten | 3.75 | S41 | 1163St 0812524976 | no | REI 60-A1 - A2,s1-d0 | 0 | BSH GL24c | AllplanAttributes - Schallschutzklasse: 52
 | H2 Ebene +1 | H | Codetext | Zimmer- und Holzbauarbeiten | 3.75 | S41 | 1163St 0812525055 | no | REI 60-A1 - A2,s1-d0 | 0 | BSH GL 24c | AllplanAttributes - Schallschutzklasse: 52
 | H2 Ebene +1 | H | Codetext | Zimmer- und Holzbauarbeiten | 3.75 | S42 | 1163St 0812516933 | no | REI 60-A1 - A2,s1-d0 | 0 | BSH GL24c
 | H2 Ebene +1 | H | Codetext | Zimmer- und Holzbauarbeiten | 3.75 | U100 | 1163St 0813764666 | no | REI 60-A1 - A2,s1-d0 | 0 | FSH Baubuche GL75
 | H2 Ebene 0 | H | Codetext | Zimmer- und Holzbauarbeiten |  | U23 | 1105St 0811623733 | no | 0 | 0 | FSH Baubuche GL75 | AllplanAttributes - Sicherheitsklasse: -
 | H2 Ebene 0 | H | Codetext | Zimmer- und Holzbauarbeiten |  | U23 | 1105St 0811623373 | no | 0 | 0 | FSH Baubuche GL75 | AllplanAttributes - Sicherheitsklasse: -
 | H2 Ebene 0 | H-ST | Codetext | Zimmer- und Holzbauarbeiten |  | U23 | 1105St 0000001810 | no | 0 | 0 | BSH GL24c | AllplanAttributes - Sicherheitsklasse: -
 | H2 Ebene 0 | H-ST | Codetext | Zimmer- und Holzbauarbeiten |  | U23 | 1105St 0000001241 | no | 0 | 0 | FSH Baubuche GL75 | AllplanAttributes - Sicherheitsklasse: -
QRO 140x5 | H2 Ebene 0 | QRO |  | Stahlbauarbeiten | 0 | S69 | 1113St 0812747170 | yes | REI 90-A1 | 0 | AllplanAttributes - Sicherheitsklasse: -; Dateiname: C:\ProgramData\Nemetschek\Allplan\2024\Etc\Library\Engineering\Steel sections\2D profiles angular idealiz\Hollow square cold finished\140 x 140 x 5.sym; Folgenname: 140 x 140 x 5; Bezeichnung: QRO 140x5
QRO 140x5 | H2 Ebene 0 | QRO |  | Stahlbauarbeiten | 0 | S66 | 1113St 0812747137 | yes | REI 90-A1 | 0 | AllplanAttributes - Sicherheitsklasse: -; Dateiname: C:\ProgramData\Nemetschek\Allplan\2024\Etc\Library\Engineering\Steel sections\2D profiles angular idealiz\Hollow square cold finished\140 x 140 x 5.sym; Folgenname: 140 x 140 x 5; Bezeichnung: QRO 140x5
QRO 140x5 | H2 Ebene 0 | QRO |  | Stahlbauarbeiten | 0 | S68 | 1113St 0812747144 | yes | REI 90-A1 | 0 | AllplanAttributes - Sicherheitsklasse: -; Dateiname: C:\ProgramData\Nemetschek\Allplan\2024\Etc\Library\Engineering\Steel sections\2D profiles angular idealiz\Hollow square cold finished\140 x 140 x 5.sym; Folgenname: 140 x 140 x 5; Bezeichnung: QRO 140x5
QRO 140x5 | H2 Ebene 0 | QRO |  | Stahlbauarbeiten | 0 | S70 | 1113St 0812747252 | yes | REI 90-A1 | 0 | AllplanAttributes - Sicherheitsklasse: -; Dateiname: C:\ProgramData\Nemetschek\Allplan\2024\Etc\Library\Engineering\Steel sections\2D profiles angular idealiz\Hollow square cold finished\140 x 140 x 5.sym; Folgenname: 140 x 140 x 5; Bezeichnung: QRO 140x5
QRO 140x5 | H2 Ebene 0 | QRO |  | Stahlbauarbeiten | 0 | S70 | 1113St 0812747203 | yes | REI 90-A1 | 0 | AllplanAttributes - Sicherheitsklasse: -; Dateiname: C:\ProgramData\Nemetschek\Allplan\2024\Etc\Library\Engineering\Steel sections\2D profiles angular idealiz\Hollow square cold finished\140 x 140 x 5.sym; Folgenname: 140 x 140 x 5; Bezeichnung: QRO 140x5
QRO 140x5 | H2 Ebene 0 | QRO |  | Stahlbauarbeiten | 0 | S69 | 1113St 0812747180 | yes | REI 90-A1 | 0 | AllplanAttributes - Sicherheitsklasse: -; Dateiname: C:\ProgramData\Nemetschek\Allplan\2024\Etc\Library\Engineering\Steel sections\2D profiles angular idealiz\Hollow square cold finished\140 x 140 x 5.sym; Folgenname: 140 x 140 x 5; Bezeichnung: QRO 140x5
QRO 140x5 | H2 Ebene 0 | QRO |  | Stahlbauarbeiten | 0 | S71 | 1113St 0812747238 | yes | REI 90-A1 | 0 | AllplanAttributes - Sicherheitsklasse: -; Dateiname: C:\ProgramData\Nemetschek\Allplan\2024\Etc\Library\Engineering\Steel sections\2D profiles angular idealiz\Hollow square cold finished\140 x 140 x 5.sym; Folgenname: 140 x 140 x 5; Bezeichnung: QRO 140x5
QRO 140x5 | H2 Ebene 0 | QRO |  | Stahlbauarbeiten | 0 | S67 | 1113St 0812747251 | yes | REI 90-A1 | 0 | AllplanAttributes - Sicherheitsklasse: -; Dateiname: C:\ProgramData\Nemetschek\Allplan\2024\Etc\Library\Engineering\Steel sections\2D profiles angular idealiz\Hollow square cold finished\140 x 140 x 5.sym; Folgenname: 140 x 140 x 5; Bezeichnung: QRO 140x5
 | H2 Ebene 0 | H-ST | Codetext | Zimmer- und Holzbauarbeiten | 0 | S61 | 1113St 0812525055 | no | REI 60-A1 - A2,s1-d0 | 0 | BSH GL24c | AllplanAttributes - Schallschutzklasse: -; Sicherheitsklasse: -
 | H2 Ebene 0 | H-ST | Codetext | Zimmer- und Holzbauarbeiten | 0 | S63 | 1113St 0813949397 | no | REI 60-A1 - A2,s1-d0 | 0 | NH C24 | AllplanAttributes - Sicherheitsklasse: -
 | H2 Ebene 0 | H-ST | Codetext | Zimmer- und Holzbauarbeiten | 0 | S63 | 1113St 0813844279 | no | REI 60-A1 - A2,s1-d0 | 0 | NH C24 | AllplanAttributes - Sicherheitsklasse: -
 | H2 Ebene 0 | H-ST | Codetext | Zimmer- und Holzbauarbeiten | 0 | S62 | 1113St 0812516933 | no | REI 60-A1 - A2,s1-d0 | 0 | BSH GL24c | AllplanAttributes - Sicherheitsklasse: -
 | H2 Ebene 0 | H-ST | Codetext | Zimmer- und Holzbauarbeiten | 0 | S62 | 1113St 0813974276 | no | REI 60-A1 - A2,s1-d0 | 0 | BSH GL24c | AllplanAttributes - Sicherheitsklasse: -
 | H2 Ebene 0 | H-ST | Codetext | Zimmer- und Holzbauarbeiten | 0 | S62 | 1113St 0812523686 | no | REI 60-A1 - A2,s1-d0 | 0 | BSH GL24c | AllplanAttributes - Sicherheitsklasse: -
 | H2 Ebene 0 | H-ST | Codetext | Zimmer- und Holzbauarbeiten | 0 | S63 | 1113St 0812442477 | no | REI 60-A1 - A2,s1-d0 | 0 | BSH GL24c | AllplanAttributes - Sicherheitsklasse: -
 | H2 Ebene 0 | H-ST | Codetext | Zimmer- und Holzbauarbeiten | 0 | S65 | 1113St 0812442474 | no | REI 60-A1 - A2,s1-d0 | 0 | BSH GL24c | AllplanAttributes - Sicherheitsklasse: -
 | H2 Ebene 0 | H-ST | Codetext | Zimmer- und Holzbauarbeiten | 0 | S64 | 1113St 0812447437 | no | REI 60-A1 - A2,s1-d0 | 0 | BSH GL24c | AllplanAttributes - Sicherheitsklasse: -
 | H2 Ebene 0 | H-ST | Codetext | Zimmer- und Holzbauarbeiten | 0 | S64 | 1113St 0812523683 | no | REI 60-A1 - A2,s1-d0 | 0 | BSH GL24c | AllplanAttributes - Sicherheitsklasse: -
 | H2 Ebene 0 | H-ST | Codetext | Zimmer- und Holzbauarbeiten | 0 | S65 | 1113St 0812523681 | no | REI 60-A1 - A2,s1-d0 | 0 | BSH GL24c | AllplanAttributes - Sicherheitsklasse: -
 | H2 Ebene 0 | H-ST | Codetext | Zimmer- und Holzbauarbeiten | 0 | S63 | 1113St 0813855752 | no | REI 60-A1 - A2,s1-d0 | 0 | NH C24 | AllplanAttributes - Sicherheitsklasse: -
 | H2 Ebene 0 | H-ST | Codetext | Zimmer- und Holzbauarbeiten | 0 | S63 | 1113St 0813855528 | no | REI 60-A1 - A2,s1-d0 | 0 | NH C24 | AllplanAttributes - Sicherheitsklasse: -
 | H2 Ebene 0 | H-ST | Codetext | Zimmer- und Holzbauarbeiten | 0 | S63 | 1113St 0812523684 | no | REI 60-A1 - A2,s1-d0 | 0 | BSH GL24c | AllplanAttributes - Sicherheitsklasse: -
 | H2 Ebene 0 | H | Codetext | Zimmer- und Holzbauarbeiten | 3.75 | U100 | 1113St 0813939251 | no | REI 60-A1 - A2,s1-d0 | 0 | FSH Baubuche GL75 | AllplanAttributes - Sicherheitsklasse: -
 | H2 Ebene 0 | H | Codetext | Zimmer- und Holzbauarbeiten | 3.75 | U100 | 1113St 0813939282 | no | REI 60-A1 - A2,s1-d0 | 0 | FSH Baubuche GL75 | AllplanAttributes - Sicherheitsklasse: -

# IfcCovering (3945)
Name | In | PredefinedType | Material | Allright_Bauteil_ID | Abrechnungsart | Gewerk | Schichtnummer | Schichtdicke (m) | Dicke (m) | Faktor | Objektname | AllplanAttributes, Material | Bezugshöhe | Deltahöhe | Status | D_lichte Raumhöhe [Zahl] (m)
Sichtbetonklasse SB3 | H2 Ebene +3 | CLADDING | 03 0.001 m | 1265Sfl0000052315/02 | m² | Putz- und Stuckarbeiten | 2 | 0.001 | 0 | 1 | Seitenfläche | 03 | 0 | 0 | NEW | AllplanAttributes - Bezeichnung: Sichtbetonklasse SB3
a-sh Abschluss Abhangdecke | H2 Ebene +3 | CEILING |  | 1265HWa0000053048 | m² |  |  |  |  |  | Gesamtwand |  |  |  | NEW | AllplanAttributes - Bezeichnung: a-sh Abschluss Abhangdecke; Attributset-Objekt: Covering; Object Layer Attributes #1, 2D Interaktion: yes; Object Layer Attributes #1, Gewerk: Trockenbauarbeiten; Object Layer Attributes #1, Material: A; Object Layer Attributes #1, Tragendes Bauteil: no; Object Layer Attributes #1, Attributset-Objekt: Covering; Object Layer Attributes #1, Allright_Bauteil_ID: 1265Wa 0000053049; Object Layer Attributes #1, Abrechnungsart: m²; Object Layer Attributes #1, Objektname: Wand; Pset_CoveringCommon - IsExternal: no; FireRating: -; ThermalTransmittance: 0 W/K/m2; Reference: Reference
a-sh Abschluss Abhangdecke | H2 Ebene +3 | CEILING |  | 1265HWa0000053053 | m² |  |  |  |  |  | Gesamtwand |  |  |  | NEW | AllplanAttributes - Bezeichnung: a-sh Abschluss Abhangdecke; Attributset-Objekt: Covering; Object Layer Attributes #1, 2D Interaktion: yes; Object Layer Attributes #1, Gewerk: Trockenbauarbeiten; Object Layer Attributes #1, Material: A; Object Layer Attributes #1, Tragendes Bauteil: no; Object Layer Attributes #1, Attributset-Objekt: Covering; Object Layer Attributes #1, Allright_Bauteil_ID: 1265Wa 0000053054; Object Layer Attributes #1, Abrechnungsart: m²; Object Layer Attributes #1, Objektname: Wand; Pset_CoveringCommon - IsExternal: no; FireRating: -; ThermalTransmittance: 0 W/K/m2; Reference: Reference
PVC | WUN-H2-E03-F03 | FLOORING | Ku3 0.15 m | 1265Bfl0000000724/01 | m² | Bodenbelagsarbeiten | 1 | 0.15 | 0 | 1 | Bodenfläche | Ku3 | 0 | 0 | NEW | AllplanAttributes - Bezeichnung: PVC; Raumnr. Bauherr: 2.11_A2_02; ash B_Aufbau: B9; ash B_Rutschhemmung: R9
 | WUN-H2-E03-F03 | CEILING | Aa 0.2 m | 1265Dfl0000039092/01 | m² | Trockenbauarbeiten | 1 | 0.2 | 0 | 1 | Bekleidung | Aa | 0 | 0 | NEW | 2.5 | Pset_CoveringCommon - FireRating: F30; AcousticRating: -; AllplanAttributes - ash_lichte Raumhöhe: 2.500000
 | WUN-H2-E03-F03 | CEILING | D1 0.001 m | 1265Dfl0000039092/02 | m² | Maler- und Lackierarbeiten | 2 | 0.001 | 0 | 1 | Bekleidung | D1 | 0 | 0 | NEW | 2.5 | AllplanAttributes - ash_lichte Raumhöhe: 2.500000
 | WUN-H2-E03-F03 | CEILING | A1 0.2 m | 1265Dfl0000016053/01 | m² | Trockenbauarbeiten | 1 | 0.2 | 0 | 1 | Bekleidung | A1 | 0 | 0 | NEW | 2.5 | Pset_CoveringCommon - FireRating: F30; AcousticRating: -; AllplanAttributes - ash_lichte Raumhöhe: 2.500000
 | WUN-H2-E03-F03 | CEILING | D1 0.001 m | 1265Dfl0000016053/02 | m² | Maler- und Lackierarbeiten | 2 | 0.001 | 0 | 1 | Bekleidung | D1 | 0 | 0 | NEW | 2.5 | AllplanAttributes - ash_lichte Raumhöhe: 2.500000
Gipsfaserplatte | WUN-H2-E03-F03 | CEILING | C/C 0.036 m | 1265Dfl0000053022/01 | m² | Trockenbauarbeiten | 1 | 0.036 | 0 | 1 | Deckenfläche | C/C | 0 | 0 | NEW | AllplanAttributes - Bezeichnung: Gipsfaserplatte
Fliesen Großformat | WUN-H2-E03-T03 | FLOORING | Fl12 0.1 m | 1265Bfl0000039493/01 | m² | Bodenbelagsarbeiten | 1 | 0.1 | 0 | 1 | Bodenfläche | Fl12 | 0 | 0 | NEW | AllplanAttributes - Bezeichnung: Fliesen Großformat; ash B_Aufbau: B7; ash B_Rutschhemmung: R10
Sichtbetonklasse SB3 | WUN-H2-E03-T03 | CLADDING | 03 0.001 m | 1265Sfl0000046908/02 | m² | Putz- und Stuckarbeiten | 2 | 0.001 | 0 | 1 | Seitenfläche | 03 | 0 | 0 | NEW | AllplanAttributes - Bezeichnung: Sichtbetonklasse SB3
Sichtbetonklasse SB3 | WUN-H2-E03-T03 | CLADDING | 47 0.001 m | 1265Sfl0000046908/04 | m² | Maler- und Lackierarbeiten | 4 | 0.001 | 0 | 1 | Seitenfläche | 47 | 0 | 0 | NEW
 | WUN-H2-E03-T03 | CEILING | Installationshöhe 0.03 m | 1265Dfl0000018031/01 | m² | Trockenbauarbeiten | 1 | 0.03 | 0 | 1 | Bekleidung | Installationshöhe | 0 | 0 | NEW | 3.12 | AllplanAttributes - ash_lichte Raumhöhe: 3.120000
 | WUN-H2-E03-T03 | CEILING | A1 0.1 m | 1265Dfl0000018031/02 | m² | Trockenbauarbeiten | 2 | 0.1 | 0 | 1 | Bekleidung | A1 | 0 | 0 | NEW | 3.12 | Pset_CoveringCommon - FireRating: F60; AcousticRating: -; AllplanAttributes - ash_lichte Raumhöhe: 3.120000
 | WUN-H2-E03-T03 | CEILING | D4 0.001 m | 1265Dfl0000018031/03 | m² | Maler- und Lackierarbeiten | 3 | 0.001 | 0 | 1 | Bekleidung | D4 | 0 | 0 | NEW | 3.12 | AllplanAttributes - ash_lichte Raumhöhe: 3.120000
Gipsfaserplatte | WUN-H2-E03-T03 | CEILING | C/C 0.036 m | 1265Dfl0000000003/01 | m² | Trockenbauarbeiten | 1 | 0.036 | 0 | 1 | Bekleidung | C/C | 0 | 0 | NEW | 3.977 | AllplanAttributes - Bezeichnung: Gipsfaserplatte; ash_lichte Raumhöhe: (16508.762-36)/1000-11.25; OKFF: 11.25
PVC | WUN-H2-E03-F02 | FLOORING | Ku3 0.15 m | 1265Bfl0000000726/01 | m² | Bodenbelagsarbeiten | 1 | 0.15 | 0 | 1 | Bodenfläche | Ku3 | 0 | 0 | NEW | AllplanAttributes - Bezeichnung: PVC; Raumnr. Bauherr: 2.11_A2_02; ash B_Aufbau: B9; ash B_Rutschhemmung: R9
 | WUN-H2-E03-F02 | CEILING | A1 0.2 m | 1265Dfl0000016255/01 | m² | Trockenbauarbeiten | 1 | 0.2 | 0 | 1 | Bekleidung | A1 | 0 | 0 | NEW | 2.5 | Pset_CoveringCommon - FireRating: F30; AcousticRating: -; AllplanAttributes - ash_lichte Raumhöhe: 2.500000
 | WUN-H2-E03-F02 | CEILING | D1 0.001 m | 1265Dfl0000016255/02 | m² | Maler- und Lackierarbeiten | 2 | 0.001 | 0 | 1 | Bekleidung | D1 | 0 | 0 | NEW | 2.5 | AllplanAttributes - ash_lichte Raumhöhe: 2.500000
 | WUN-H2-E03-F02 | CEILING | Aa 0.2 m | 1265Dfl0000037253/01 | m² | Trockenbauarbeiten | 1 | 0.2 | 0 | 1 | Bekleidung | Aa | 0 | 0 | NEW | 2.5 | Pset_CoveringCommon - FireRating: F30; AcousticRating: -; AllplanAttributes - ash_lichte Raumhöhe: 2.500000
 | WUN-H2-E03-F02 | CEILING | D1 0.001 m | 1265Dfl0000037253/02 | m² | Maler- und Lackierarbeiten | 2 | 0.001 | 0 | 1 | Bekleidung | D1 | 0 | 0 | NEW | 2.5 | AllplanAttributes - ash_lichte Raumhöhe: 2.500000
Gipsfaserplatte | WUN-H2-E03-F02 | CEILING | C/C 0.036 m | 1265Dfl0000053023/01 | m² | Trockenbauarbeiten | 1 | 0.036 | 0 | 1 | Deckenfläche | C/C | 0 | 0 | NEW | AllplanAttributes - Bezeichnung: Gipsfaserplatte
PVC | WUN-H2-E03-F01 | FLOORING | Ku3 0.15 m | 1265Bfl0000000725/01 | m² | Bodenbelagsarbeiten | 1 | 0.15 | 0 | 1 | Bodenfläche | Ku3 | 0 | 0 | NEW | AllplanAttributes - Bezeichnung: PVC; Raumnr. Bauherr: 2.11_A2_02; ash B_Aufbau: B9; ash B_Rutschhemmung: R9
 | WUN-H2-E03-F01 | CEILING | Aa 0.15 m | 1265Dfl0000038665/01 | m² | Trockenbauarbeiten | 1 | 0.15 | 0 | 1 | Bekleidung | Aa | 0 | 0 | NEW | 2.5 | Pset_CoveringCommon - FireRating: F30; AcousticRating: -; AllplanAttributes - ash_lichte Raumhöhe: 2.550000
 | WUN-H2-E03-F01 | CEILING | D1 0.001 m | 1265Dfl0000038665/02 | m² | Maler- und Lackierarbeiten | 2 | 0.001 | 0 | 1 | Bekleidung | D1 | 0 | 0 | NEW | 2.5 | AllplanAttributes - ash_lichte Raumhöhe: 2.550000
 | WUN-H2-E03-F01 | CEILING | A1 0.15 m | 1265Dfl0000016154/01 | m² | Trockenbauarbeiten | 1 | 0.15 | 0 | 1 | Bekleidung | A1 | 0 | 0 | NEW | 2.5 | Pset_CoveringCommon - FireRating: F30; AcousticRating: -; AllplanAttributes - ash_lichte Raumhöhe: 2.550000
 | WUN-H2-E03-F01 | CEILING | D1 0.001 m | 1265Dfl0000016154/02 | m² | Maler- und Lackierarbeiten | 2 | 0.001 | 0 | 1 | Bekleidung | D1 | 0 | 0 | NEW | 2.5 | AllplanAttributes - ash_lichte Raumhöhe: 2.550000
Gipsfaserplatte | WUN-H2-E03-F01 | CEILING | C/C 0.036 m | 1265Dfl0000053025/01 | m² | Trockenbauarbeiten | 1 | 0.036 | 0 | 1 | Deckenfläche | C/C | 0 | 0 | NEW | AllplanAttributes - Bezeichnung: Gipsfaserplatte
Fliesen Großformat | WUN-H2-E03-T01 | FLOORING | Fl12 0.15 m | 1265Bfl0000040599/01 | m² | Bodenbelagsarbeiten | 1 | 0.15 | 0 | 1 | Bodenfläche | Fl12 | 0 | 0 | NEW | AllplanAttributes - Bezeichnung: Fliesen Großformat; ash B_Aufbau: B8; ash B_Rutschhemmung: R10
Sichtbetonklasse SB3 | WUN-H2-E03-T01 | CLADDING | 03 0.001 m | 1265Sfl0000046907/02 | m² | Putz- und Stuckarbeiten | 2 | 0.001 | 0 | 1 | Seitenfläche | 03 | 0 | 0 | NEW | AllplanAttributes - Bezeichnung: Sichtbetonklasse SB3
Sichtbetonklasse SB3 | WUN-H2-E03-T01 | CLADDING | 47 0.001 m | 1265Sfl0000046907/04 | m² | Maler- und Lackierarbeiten | 4 | 0.001 | 0 | 1 | Seitenfläche | 47 | 0 | 0 | NEW
Gipsfaserplatte | WUN-H2-E03-T01 | CEILING | C/C 0.036 m | 1265Dfl0000053024/01 | m² | Trockenbauarbeiten | 1 | 0.036 | 0 | 1 | Deckenfläche | C/C | 0 | 0 | NEW | AllplanAttributes - Bezeichnung: Gipsfaserplatte
 | WUN-H2-E03-T01 | CEILING | A1 0.1 m | 1265Dfl0000043826/01 | m² | Trockenbauarbeiten | 1 | 0.1 | 0 | 1 | Bekleidung | A1 | 0 | 0 | NEW | 2.5 | Pset_CoveringCommon - FireRating: F60; AcousticRating: -; AllplanAttributes - ash_lichte Raumhöhe: 2.500000
 | WUN-H2-E03-T01 | CEILING | D1 0.001 m | 1265Dfl0000043826/02 | m² | Maler- und Lackierarbeiten | 2 | 0.001 | 0 | 1 | Bekleidung | D1 | 0 | 0 | NEW | 2.5 | AllplanAttributes - ash_lichte Raumhöhe: 2.500000
 | WUN-H2-E03-T01 | CEILING | A1 0.1 m | 1265Dfl0000040017/01 | m² | Trockenbauarbeiten | 1 | 0.1 | 0 | 1 | Bekleidung | A1 | 0 | 0 | NEW | 2.7 | Pset_CoveringCommon - FireRating: F60; AcousticRating: -; AllplanAttributes - ash_lichte Raumhöhe: 3.100000
 | WUN-H2-E03-T01 | CEILING | D1 0.001 m | 1265Dfl0000040017/02 | m² | Maler- und Lackierarbeiten | 2 | 0.001 | 0 | 1 | Bekleidung | D1 | 0 | 0 | NEW | 2.7 | AllplanAttributes - ash_lichte Raumhöhe: 3.100000
Beschichtung allgemein | WUN-H2-E03-019a | FLOORING | Ba 0.15 m | 1266Bfl0812715620/01 | m² | Bodenbelagsarbeiten | 1 | 0.15 | 0 | 1 | Bodenfläche | Ba | 0 | 0 | NEW | AllplanAttributes - Bezeichnung: Beschichtung allgemein; Raumnr. Bauherr: 2.11_A2_02; ash B_Aufbau: B12; ash B_Rutschhemmung: R9
Gipsfaserplatte | WUN-H2-E03-019a | CEILING | C/C 0.036 m | 1266Dfl0812715619/01 | m² | Trockenbauarbeiten | 1 | 0.036 | 0 | 1 | Deckenfläche | C/C | 0 | 0 | NEW | AllplanAttributes - Bezeichnung: Gipsfaserplatte
Gipsfaserplatte | WUN-H2-E03-019a | CEILING | D4 0.001 m | 1266Dfl0812715619/02 | m² | Maler- und Lackierarbeiten | 2 | 0.001 | 0 | 1 | Bekleidung | D4 | 0 | 0 | NEW | 4.001 | AllplanAttributes - ash_lichte Raumhöhe: 3.348275; OKFF: 5.11
Beschichtung allgemein | WUN-H2-E03-019a | FLOORING | Ba 0.15 m | 1266Bfl0812715575/01 | m² | Bodenbelagsarbeiten | 1 | 0.15 | 0 | 1 | Bodenfläche | Ba | 0 | 0 | NEW | AllplanAttributes - Bezeichnung: Beschichtung allgemein; Raumnr. Bauherr: 2.11_A2_02; ash B_Aufbau: B12; ash B_Rutschhemmung: R9
Gipsfaserplatte | WUN-H2-E03-019a | CEILING | C/C 0.036 m | 1266Dfl0812715574/01 | m² | Trockenbauarbeiten | 1 | 0.036 | 0 | 1 | Deckenfläche | C/C | 0 | 0 | NEW | AllplanAttributes - Bezeichnung: Gipsfaserplatte
Gipsfaserplatte | WUN-H2-E03-019a | CEILING | D4 0.001 m | 1266Dfl0812715574/02 | m² | Maler- und Lackierarbeiten | 2 | 0.001 | 0 | 1 | Bekleidung | D4 | 0 | 0 | NEW | 4.001 | AllplanAttributes - ash_lichte Raumhöhe: 3.478779; OKFF: 5.11
Beschichtung allgemein | WUN-H2-E03-011 | FLOORING | Ba 0.15 m | 1266Bfl0000012838/01 | m² | Bodenbelagsarbeiten | 1 | 0.15 | 0 | 1 | Bodenfläche | Ba | 0 | 0 | NEW | AllplanAttributes - Bezeichnung: Beschichtung allgemein; Raumnr. Bauherr: 2.11_A2_02; ash B_Aufbau: B12; ash B_Rutschhemmung: R9
Gipsfaserplatte | WUN-H2-E03-011 | CEILING | C/C 0.036 m | 1266Dfl0812717204/01 | m² | Trockenbauarbeiten | 1 | 0.036 | 0 | 1 | Deckenfläche | C/C | 0 | 0 | NEW | AllplanAttributes - Bezeichnung: Gipsfaserplatte
Gipsfaserplatte | WUN-H2-E03-011 | CEILING | D4 0.001 m | 1266Dfl0812717204/02 | m² | Maler- und Lackierarbeiten | 2 | 0.001 | 0 | 1 | Bekleidung | D4 | 0 | 0 | NEW | 4.001 | AllplanAttributes - ash_lichte Raumhöhe: 3.972558; OKFF: 5.11
PVC | WUN-H2-E03-020 | FLOORING | Ku3 0.15 m | 1266Bfl0000012865/01 | m² | Bodenbelagsarbeiten | 1 | 0.15 | 0 | 1 | Bodenfläche | Ku3 | 0 | 0 | NEW | AllplanAttributes - Bezeichnung: PVC; Raumnr. Bauherr: 2.11_A2_02; ash B_Aufbau: B9; ash B_Rutschhemmung: R9
Gipsfaserplatte | WUN-H2-E03-020 | CEILING | C/C 0.036 m | 1266Dfl0812638966/01 | m² | Trockenbauarbeiten | 1 | 0.036 | 0 | 1 | Deckenfläche | C/C | 0 | 0 | NEW | AllplanAttributes - Bezeichnung: Gipsfaserplatte
Gipsfaserplatte | WUN-H2-E03-020 | CEILING | D4 0.001 m | 1266Dfl0812638966/02 | m² | Maler- und Lackierarbeiten | 2 | 0.001 | 0 | 1 | Bekleidung | D4 | 0 | 0 | NEW | 4.001 | AllplanAttributes - ash_lichte Raumhöhe: 4.130686; OKFF: 5.11
PVC | WUN-H2-E03-017-A | FLOORING | Ku3 0.15 m | 1266Bfl0812643066/01 | m² | Bodenbelagsarbeiten | 1 | 0.15 | 0 | 1 | Bodenfläche | Ku3 | 0 | 0 | NEW | AllplanAttributes - Bezeichnung: PVC; Raumnr. Bauherr: 2.11_A2_02; ash B_Aufbau: B9; ash B_Rutschhemmung: R9
Gipsfaserplatte | WUN-H2-E03-017-A | CEILING | C/C 0.036 m | 1266Dfl0812692510/01 | m² | Trockenbauarbeiten | 1 | 0.036 | 0 | 1 | Deckenfläche | C/C | 0 | 0 | NEW | AllplanAttributes - Bezeichnung: Gipsfaserplatte
Gipsfaserplatte | WUN-H2-E03-017-A | CEILING | D4 0.001 m | 1266Dfl0812692510/02 | m² | Maler- und Lackierarbeiten | 2 | 0.001 | 0 | 1 | Bekleidung | D4 | 0 | 0 | NEW | 3.324 | AllplanAttributes - ash_lichte Raumhöhe: 3.273293; OKFF: 5.11
PVC | WUN-H2-E03-017-B | FLOORING | Ku3 0.15 m | 1266Bfl0812714452/01 | m² | Bodenbelagsarbeiten | 1 | 0.15 | 0 | 1 | Bodenfläche | Ku3 | 0 | 0 | NEW | AllplanAttributes - Bezeichnung: PVC; Raumnr. Bauherr: 2.11_A2_02; ash B_Aufbau: B9; ash B_Rutschhemmung: R9
Gipsfaserplatte | WUN-H2-E03-017-B | CEILING | C/C 0.036 m | 1266Dfl0812690262/01 | m² | Trockenbauarbeiten | 1 | 0.036 | 0 | 1 | Deckenfläche | C/C | 0 | 0 | NEW | AllplanAttributes - Bezeichnung: Gipsfaserplatte
Gipsfaserplatte | WUN-H2-E03-017-B | CEILING | D4 0.001 m | 1266Dfl0812690262/02 | m² | Maler- und Lackierarbeiten | 2 | 0.001 | 0 | 1 | Bekleidung | D4 | 0 | 0 | NEW | 3.324 | AllplanAttributes - ash_lichte Raumhöhe: 3.210387; OKFF: 5.11
Beschichtung ölfest | WUN-H2-E03-018 | FLOORING | Bö 0.15 m | 1266Bfl0000012759/01 | m² | Bodenbelagsarbeiten | 1 | 0.15 | 0 | 1 | Bodenfläche | Bö | 0 | 0 | NEW | AllplanAttributes - Bezeichnung: Beschichtung ölfest; Raumnr. Bauherr: 2.11_A2_02; ash B_Aufbau: B12; ash B_Rutschhemmung: R10
Gipsfaserplatte | WUN-H2-E03-018 | CEILING | C/C 0.036 m | 1266Dfl0812692505/01 | m² | Trockenbauarbeiten | 1 | 0.036 | 0 | 1 | Deckenfläche | C/C | 0 | 0 | NEW | AllplanAttributes - Bezeichnung: Gipsfaserplatte
Gipsfaserplatte | WUN-H2-E03-018 | CEILING | D4 0.001 m | 1266Dfl0812692505/02 | m² | Maler- und Lackierarbeiten | 2 | 0.001 | 0 | 1 | Bekleidung | D4 | 0 | 0 | NEW | 3.324 | AllplanAttributes - ash_lichte Raumhöhe: 3.211808; OKFF: 5.11
Beschichtung ölfest | WUN-H2-E03-007 | FLOORING | Bö 0.15 m | 1266Bfl0000012742/01 | m² | Bodenbelagsarbeiten | 1 | 0.15 | 0 | 1 | Bodenfläche | Bö | 0 | 0 | NEW | AllplanAttributes - Bezeichnung: Beschichtung ölfest; Raumnr. Bauherr: 2.11_A2_02; ash B_Aufbau: B12; ash B_Rutschhemmung: R10
Gipsfaserplatte | WUN-H2-E03-007 | CEILING | C/C 0.036 m | 1266Dfl0000012741/01 | m² | Trockenbauarbeiten | 1 | 0.036 | 0 | 1 | Deckenfläche | C/C | 0 | 0 | NEW | AllplanAttributes - Bezeichnung: Gipsfaserplatte
Gipsfaserplatte | WUN-H2-E03-007 | CEILING | D4 0.001 m | 1266Dfl0000012741/02 | m² | Maler- und Lackierarbeiten | 2 | 0.001 | 0 | 1 | Bekleidung | D4 | 0 | 0 | NEW | 3.324 | AllplanAttributes - ash_lichte Raumhöhe: 3.374330; OKFF: 5.11
Beschichtung allgemein | WUN-H2-E03-013 | FLOORING | Ba 0.15 m | 1266Bfl0000012902/01 | m² | Bodenbelagsarbeiten | 1 | 0.15 | 0 | 1 | Bodenfläche | Ba | 0 | 0 | NEW | AllplanAttributes - Bezeichnung: Beschichtung allgemein; Raumnr. Bauherr: 2.11_A2_02; ash B_Aufbau: B12; ash B_Rutschhemmung: R9
Gipsfaserplatte | WUN-H2-E03-013 | CEILING | C/C 0.036 m | 1266Dfl0000012903/01 | m² | Trockenbauarbeiten | 1 | 0.036 | 0 | 1 | Deckenfläche | C/C | 0 | 0 | NEW | AllplanAttributes - Bezeichnung: Gipsfaserplatte
Gipsfaserplatte | WUN-H2-E03-013 | CEILING | D4 0.001 m | 1266Dfl0000012903/02 | m² | Maler- und Lackierarbeiten | 2 | 0.001 | 0 | 1 | Bekleidung | D4 | 0 | 0 | NEW | 4.001 | AllplanAttributes - ash_lichte Raumhöhe: 5.470700; OKFF: 5.11
Beschichtung allgemein | WUN-H2-E03-014 | FLOORING | Ba 0.1 m | 1266Bfl0000013431/01 | m² | Bodenbelagsarbeiten | 1 | 0.1 | 0 | 1 | Bodenfläche | Ba | 0 | 0 | NEW | AllplanAttributes - Bezeichnung: Beschichtung allgemein; Raumnr. Bauherr: 2.11_A2_02; ash B_Aufbau: B12; ash B_Rutschhemmung: R9
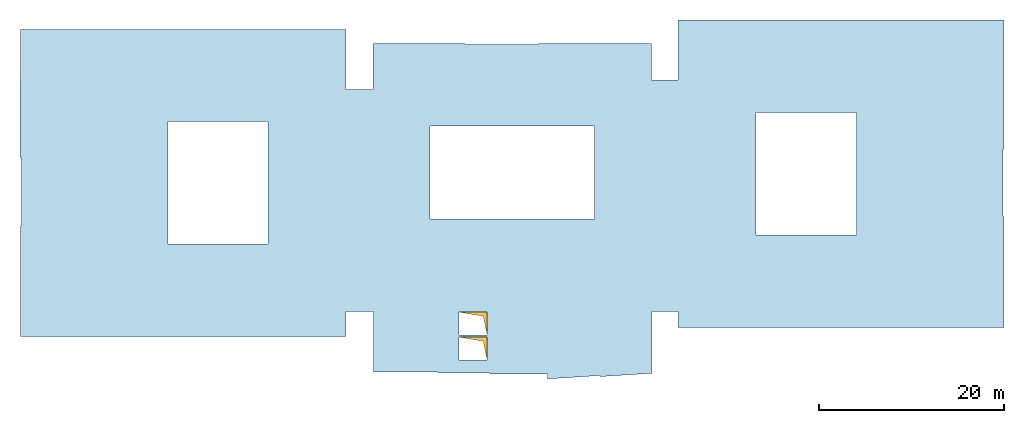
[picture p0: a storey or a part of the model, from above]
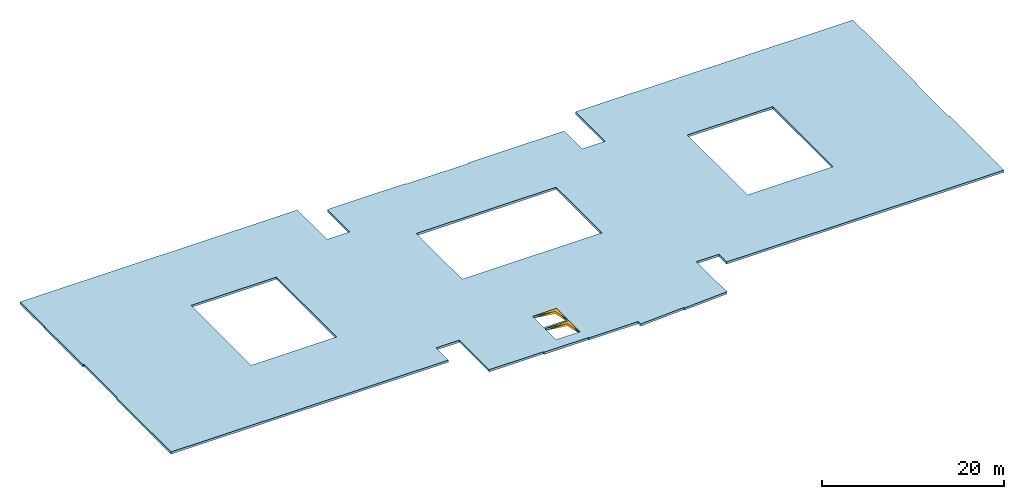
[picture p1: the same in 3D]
Properties of the parts of a building model (IFC4), part 5 of 80

# IfcCovering (3945)
Name | In | PredefinedType | Material | Allright_Bauteil_ID | Abrechnungsart | Gewerk | Schichtnummer | Schichtdicke (m) | Dicke (m) | Faktor | Objektname | AllplanAttributes, Material | Bezugshöhe | Deltahöhe | Status | D_lichte Raumhöhe [Zahl] (m)
Gipsfaserplatte | WUN-H2-E03-014 | CEILING | C/C 0.036 m | 1266Dfl0000013430/01 | m² | Trockenbauarbeiten | 1 | 0.036 | 0 | 1 | Deckenfläche | C/C | 0 | 0 | NEW | AllplanAttributes - Bezeichnung: Gipsfaserplatte
Gipsfaserplatte | WUN-H2-E03-014 | CEILING | D4 0.001 m | 1266Dfl0000013430/02 | m² | Maler- und Lackierarbeiten | 2 | 0.001 | 0 | 1 | Bekleidung | D4 | 0 | 0 | NEW | 4.001 | AllplanAttributes - ash_lichte Raumhöhe: 4.346381; OKFF: 5.11
Beschichtung allgemein | WUN-H2-E03-004 | FLOORING | Ba 0.15 m | 1266Bfl0000012771/01 | m² | Bodenbelagsarbeiten | 1 | 0.15 | 0 | 1 | Bodenfläche | Ba | 0 | 0 | NEW | AllplanAttributes - Bezeichnung: Beschichtung allgemein; Raumnr. Bauherr: 2.11_A2_02; ash B_Aufbau: B12; ash B_Rutschhemmung: R9
Gipsfaserplatte | WUN-H2-E03-004 | CEILING | C/C 0.036 m | 1266Dfl0812604125/01 | m² | Trockenbauarbeiten | 1 | 0.036 | 0 | 1 | Deckenfläche | C/C | 0 | 0 | NEW | AllplanAttributes - Bezeichnung: Gipsfaserplatte
Gipsfaserplatte | WUN-H2-E03-004 | CEILING | D4 0.001 m | 1266Dfl0812604125/02 | m² | Maler- und Lackierarbeiten | 2 | 0.001 | 0 | 1 | Bekleidung | D4 | 0 | 0 | NEW | 4.001 | AllplanAttributes - ash_lichte Raumhöhe: 3.688808; OKFF: 5.11
Beschichtung allgemein | WUN-H2-E03-016 | FLOORING | Ba 0.1 m | 1266Bfl0000013382/01 | m² | Bodenbelagsarbeiten | 1 | 0.1 | 0 | 1 | Bodenfläche | Ba | 0 | 0 | NEW | AllplanAttributes - Bezeichnung: Beschichtung allgemein; Raumnr. Bauherr: 2.11_A2_02; ash B_Aufbau: B12; ash B_Rutschhemmung: R9
Gipsfaserplatte | WUN-H2-E03-016 | CEILING | C/C 0.036 m | 1266Dfl0000013381/01 | m² | Trockenbauarbeiten | 1 | 0.036 | 0 | 1 | Deckenfläche | C/C | 0 | 0 | NEW | AllplanAttributes - Bezeichnung: Gipsfaserplatte
Gipsfaserplatte | WUN-H2-E03-016 | CEILING | D4 0.001 m | 1266Dfl0000013381/02 | m² | Maler- und Lackierarbeiten | 2 | 0.001 | 0 | 1 | Bekleidung | D4 | 0 | 0 | NEW | 4.001 | AllplanAttributes - ash_lichte Raumhöhe: 4.340158; OKFF: 5.11
Beschichtung allgemein | WUN-H2-E03-001 | FLOORING | Ba 0.15 m | 1266Bfl0000012785/01 | m² | Bodenbelagsarbeiten | 1 | 0.15 | 0 | 1 | Bodenfläche | Ba | 0 | 0 | NEW | AllplanAttributes - Bezeichnung: Beschichtung allgemein; Raumnr. Bauherr: 2.11_A2_02; ash B_Aufbau: B12; ash B_Rutschhemmung: R9
Gipsfaserplatte | WUN-H2-E03-001 | CEILING | C/C 0.036 m | 1266Dfl0812606177/01 | m² | Trockenbauarbeiten | 1 | 0.036 | 0 | 1 | Deckenfläche | C/C | 0 | 0 | NEW | AllplanAttributes - Bezeichnung: Gipsfaserplatte
Gipsfaserplatte | WUN-H2-E03-001 | CEILING | D4 0.001 m | 1266Dfl0812606177/02 | m² | Maler- und Lackierarbeiten | 2 | 0.001 | 0 | 1 | Bekleidung | D4 | 0 | 0 | NEW | 4.001 | AllplanAttributes - ash_lichte Raumhöhe: 3.767221; OKFF: 5.11
Beschichtung allgemein | WUN-H2-E03-002 | FLOORING | Ba 0.15 m | 1266Bfl0000012853/01 | m² | Bodenbelagsarbeiten | 1 | 0.15 | 0 | 1 | Bodenfläche | Ba | 0 | 0 | NEW | AllplanAttributes - Bezeichnung: Beschichtung allgemein; Raumnr. Bauherr: 2.11_A2_02; ash B_Aufbau: B12; ash B_Rutschhemmung: R9
Gipsfaserplatte | WUN-H2-E03-002 | CEILING | C/C 0.036 m | 1266Dfl0812606178/01 | m² | Trockenbauarbeiten | 1 | 0.036 | 0 | 1 | Deckenfläche | C/C | 0 | 0 | NEW | AllplanAttributes - Bezeichnung: Gipsfaserplatte
Gipsfaserplatte | WUN-H2-E03-002 | CEILING | D4 0.001 m | 1266Dfl0812606178/02 | m² | Maler- und Lackierarbeiten | 2 | 0.001 | 0 | 1 | Bekleidung | D4 | 0 | 0 | NEW | 4.001 | AllplanAttributes - ash_lichte Raumhöhe: 5.267341; OKFF: 5.11
Beschichtung ölfest | WUN-H2-E03-006 | FLOORING | Bö 0.15 m | 1266Bfl0000012747/01 | m² | Bodenbelagsarbeiten | 1 | 0.15 | 0 | 1 | Bodenfläche | Bö | 0 | 0 | NEW | AllplanAttributes - Bezeichnung: Beschichtung ölfest; Raumnr. Bauherr: 2.11_A2_02; ash B_Aufbau: B12; ash B_Rutschhemmung: R10
Gipsfaserplatte | WUN-H2-E03-006 | CEILING | C/C 0.036 m | 1266Dfl0000012746/01 | m² | Trockenbauarbeiten | 1 | 0.036 | 0 | 1 | Deckenfläche | C/C | 0 | 0 | NEW | AllplanAttributes - Bezeichnung: Gipsfaserplatte
Gipsfaserplatte | WUN-H2-E03-006 | CEILING | D4 0.001 m | 1266Dfl0000012746/02 | m² | Maler- und Lackierarbeiten | 2 | 0.001 | 0 | 1 | Bekleidung | D4 | 0 | 0 | NEW | 3.324 | AllplanAttributes - ash_lichte Raumhöhe: 3.372265; OKFF: 5.11
Gipsfaserplatte | WUN-H2-E03-010b | CEILING | C/C 0.036 m | 1266Dfl0812649266/01 | m² | Trockenbauarbeiten | 1 | 0.036 | 0 | 1 | Deckenfläche | C/C | 0 | 0 | NEW | AllplanAttributes - Bezeichnung: Gipsfaserplatte
Fliesen | WUN-H2-E03-010b | FLOORING | Fl1 0.15 m | 1266Bfl0000012939/01 | m² | Bodenbelagsarbeiten | 1 | 0.15 | 0 | 1 | Bodenfläche | Fl1 | 0 | 0 | NEW | AllplanAttributes - Bezeichnung: Fliesen; Raumnr. Bauherr: 2.11_A2_02; ash B_Aufbau: B10; ash B_Rutschhemmung: R10
Fliesen Mosaik | WUN-H2-E03-010b | FLOORING | Fl2 0.15 m | 1266Bfl0812714858/01 | m² | Bodenbelagsarbeiten | 1 | 0.15 | 0 | 1 | Bodenfläche | Fl2 | 0 | 0 | NEW | AllplanAttributes - Bezeichnung: Fliesen Mosaik; Raumnr. Bauherr: 2.11_A2_02; ash B_Aufbau: B11; ash B_Rutschhemmung: R10; ash B_Bewertungsgruppe Barfußbereich: B
 | WUN-H2-E03-010b | CEILING | Installationshöhe 0 m | 1266Dfl0812610235/01 | m² | Trockenbauarbeiten | 1 | 0 | 0 | 1 | Bekleidung | Installationshöhe | 0 | 0 | NEW | 2.5 | Pset_CoveringCommon - FireRating: für korrekte FläVisu; AllplanAttributes - ash_lichte Raumhöhe: (13900-150)/1000-11.25
Rasterdecke | WUN-H2-E03-010b | CEILING | E3 0.15 m | 1266Dfl0812610235/02 | m² | Trockenbauarbeiten | 2 | 0.15 | 0 | 1 | Bekleidung | E3 | 0 | 0 | NEW | 2.5 | AllplanAttributes - Bezeichnung: Rasterdecke; ash_lichte Raumhöhe: (13900-150)/1000-11.25; Pset_CoveringCommon - FireRating: -; AcousticRating: -
Fliesen | WUN-H2-E03-010a | FLOORING | Fl1 0.15 m | 1266Bfl0000015338/01 | m² | Bodenbelagsarbeiten | 1 | 0.15 | 0 | 1 | Bodenfläche | Fl1 | 0 | 0 | NEW | AllplanAttributes - Bezeichnung: Fliesen; Raumnr. Bauherr: 2.11_A2_02; ash B_Aufbau: B10; ash B_Rutschhemmung: R10
Gipsfaserplatte | WUN-H2-E03-010a | CEILING | C/C 0.036 m | 1266Dfl0812721450/01 | m² | Trockenbauarbeiten | 1 | 0.036 | 0 | 1 | Deckenfläche | C/C | 0 | 0 | NEW | AllplanAttributes - Bezeichnung: Gipsfaserplatte
 | WUN-H2-E03-010a | CEILING | Installationshöhe 0 m | 1266Dfl0812624528/01 | m² | Trockenbauarbeiten | 1 | 0 | 0 | 1 | Bekleidung | Installationshöhe | 0 | 0 | NEW | 2.5 | Pset_CoveringCommon - FireRating: für korrekte FläVisu; AllplanAttributes - ash_lichte Raumhöhe: (13900-150)/1000-11.25
Rasterdecke | WUN-H2-E03-010a | CEILING | E3 0.15 m | 1266Dfl0812624528/02 | m² | Trockenbauarbeiten | 2 | 0.15 | 0 | 1 | Bekleidung | E3 | 0 | 0 | NEW | 2.5 | AllplanAttributes - Bezeichnung: Rasterdecke; ash_lichte Raumhöhe: (13900-150)/1000-11.25; Pset_CoveringCommon - FireRating: -; AcousticRating: -
Fliesen Mosaik | WUN-H2-E03-009a | FLOORING | Fl2 0.15 m | 1266Bfl0812714458/01 | m² | Bodenbelagsarbeiten | 1 | 0.15 | 0 | 1 | Bodenfläche | Fl2 | 0 | 0 | NEW | AllplanAttributes - Bezeichnung: Fliesen Mosaik; Raumnr. Bauherr: 2.11_A2_02; ash B_Aufbau: B11; ash B_Rutschhemmung: R10; ash B_Bewertungsgruppe Barfußbereich: B
Fliesen | WUN-H2-E03-009a | FLOORING | Fl1 0.15 m | 1266Bfl0000015352/01 | m² | Bodenbelagsarbeiten | 1 | 0.15 | 0 | 1 | Bodenfläche | Fl1 | 0 | 0 | NEW | AllplanAttributes - Bezeichnung: Fliesen; Raumnr. Bauherr: 2.11_A2_02; ash B_Aufbau: B10; ash B_Rutschhemmung: R10
Gipsfaserplatte | WUN-H2-E03-009a | CEILING | C/C 0.036 m | 1266Dfl0812721451/01 | m² | Trockenbauarbeiten | 1 | 0.036 | 0 | 1 | Deckenfläche | C/C | 0 | 0 | NEW | AllplanAttributes - Bezeichnung: Gipsfaserplatte
 | WUN-H2-E03-009a | CEILING | Installationshöhe 0 m | 1266Dfl0812601313/01 | m² | Trockenbauarbeiten | 1 | 0 | 0 | 1 | Bekleidung | Installationshöhe | 0 | 0 | NEW | 2.5 | Pset_CoveringCommon - FireRating: für korrekte FläVisu; AllplanAttributes - ash_lichte Raumhöhe: (13900-150)/1000-11.25
Rasterdecke | WUN-H2-E03-009a | CEILING | E3 0.15 m | 1266Dfl0812601313/02 | m² | Trockenbauarbeiten | 2 | 0.15 | 0 | 1 | Bekleidung | E3 | 0 | 0 | NEW | 2.5 | AllplanAttributes - Bezeichnung: Rasterdecke; ash_lichte Raumhöhe: (13900-150)/1000-11.25; Pset_CoveringCommon - FireRating: -; AcousticRating: -
Fliesen Mosaik | WUN-H2-E03-010c | FLOORING | Fl2 0.15 m | 1266Bfl0812714658/01 | m² | Bodenbelagsarbeiten | 1 | 0.15 | 0 | 1 | Bodenfläche | Fl2 | 0 | 0 | NEW | AllplanAttributes - Bezeichnung: Fliesen Mosaik; Raumnr. Bauherr: 2.11_A2_02; ash B_Aufbau: B11; ash B_Rutschhemmung: R10; ash B_Bewertungsgruppe Barfußbereich: B
Gipsfaserplatte | WUN-H2-E03-010c | CEILING | C/C 0.036 m | 1266Dfl0812666801/01 | m² | Trockenbauarbeiten | 1 | 0.036 | 0 | 1 | Bekleidung | C/C | 0 | 0 | NEW | 3.587 | AllplanAttributes - Bezeichnung: Gipsfaserplatte; ash_lichte Raumhöhe: (15452.129-36)/1000-11.25; Pset_CoveringCommon - FireRating: für korrekte FläVisu
Fliesen | WUN-H2-E03-010c | FLOORING | Fl1 0.15 m | 1266Bfl0812666798/01 | m² | Bodenbelagsarbeiten | 1 | 0.15 | 0 | 1 | Bodenfläche | Fl1 | 0 | 0 | NEW | AllplanAttributes - Bezeichnung: Fliesen; Raumnr. Bauherr: 2.11_A2_02; ash B_Aufbau: B10; ash B_Rutschhemmung: R10
 | WUN-H2-E03-010c | CEILING | Installationshöhe 0 m | 1266Dfl0812666903/01 | m² | Trockenbauarbeiten | 1 | 0 | 0 | 1 | Bekleidung | Installationshöhe | 0 | 0 | NEW | 2.5 | Pset_CoveringCommon - FireRating: für korrekte FläVisu; AllplanAttributes - ash_lichte Raumhöhe: (13900-150)/1000-11.25
Rasterdecke | WUN-H2-E03-010c | CEILING | E3 0.15 m | 1266Dfl0812666903/02 | m² | Trockenbauarbeiten | 2 | 0.15 | 0 | 1 | Bekleidung | E3 | 0 | 0 | NEW | 2.5 | AllplanAttributes - Bezeichnung: Rasterdecke; ash_lichte Raumhöhe: (13900-150)/1000-11.25; Pset_CoveringCommon - FireRating: -; AcousticRating: -
Beschichtung allgemein | WUN-H2-E03-008 | FLOORING | Ba 0.15 m | 1266Bfl0000015415/01 | m² | Bodenbelagsarbeiten | 1 | 0.15 | 0 | 1 | Bodenfläche | Ba | 0 | 0 | NEW | AllplanAttributes - Bezeichnung: Beschichtung allgemein; Raumnr. Bauherr: 2.11_A2_02; ash B_Aufbau: B12; ash B_Rutschhemmung: R9
Gipsfaserplatte | WUN-H2-E03-008 | CEILING | C/C 0.036 m | 1266Dfl0812721452/01 | m² | Trockenbauarbeiten | 1 | 0.036 | 0 | 1 | Deckenfläche | C/C | 0 | 0 | NEW | AllplanAttributes - Bezeichnung: Gipsfaserplatte
 | WUN-H2-E03-008 | CEILING | Installationshöhe 0 m | 1266Dfl0812602482/01 | m² | Trockenbauarbeiten | 1 | 0 | 0 | 1 | Bekleidung | Installationshöhe | 0 | 0 | NEW | 2.5 | Pset_CoveringCommon - FireRating: für korrekte FläVisu; AllplanAttributes - ash_lichte Raumhöhe: (13900-150)/1000-11.25
Rasterdecke | WUN-H2-E03-008 | CEILING | E3 0.15 m | 1266Dfl0812602482/02 | m² | Trockenbauarbeiten | 2 | 0.15 | 0 | 1 | Bekleidung | E3 | 0 | 0 | NEW | 2.5 | AllplanAttributes - Bezeichnung: Rasterdecke; ash_lichte Raumhöhe: (13900-150)/1000-11.25; Pset_CoveringCommon - FireRating: -; AcousticRating: -
Fliesen | WUN-H2-E03-010 | FLOORING | Fl1 0.15 m | 1266Bfl0000015292/01 | m² | Bodenbelagsarbeiten | 1 | 0.15 | 0 | 1 | Bodenfläche | Fl1 | 0 | 0 | NEW | AllplanAttributes - Bezeichnung: Fliesen; Raumnr. Bauherr: 2.11_A2_02; ash B_Aufbau: B10; ash B_Rutschhemmung: R10
Gipsfaserplatte | WUN-H2-E03-010 | CEILING | C/C 0.036 m | 1266Dfl0812721453/01 | m² | Trockenbauarbeiten | 1 | 0.036 | 0 | 1 | Deckenfläche | C/C | 0 | 0 | NEW | AllplanAttributes - Bezeichnung: Gipsfaserplatte
 | WUN-H2-E03-010 | CEILING | Installationshöhe 0 m | 1266Dfl0812609075/01 | m² | Trockenbauarbeiten | 1 | 0 | 0 | 1 | Bekleidung | Installationshöhe | 0 | 0 | NEW | 2.5 | Pset_CoveringCommon - FireRating: für korrekte FläVisu; AllplanAttributes - ash_lichte Raumhöhe: (13900-150)/1000-11.25
Rasterdecke | WUN-H2-E03-010 | CEILING | E3 0.15 m | 1266Dfl0812609075/02 | m² | Trockenbauarbeiten | 2 | 0.15 | 0 | 1 | Bekleidung | E3 | 0 | 0 | NEW | 2.5 | AllplanAttributes - Bezeichnung: Rasterdecke; ash_lichte Raumhöhe: (13900-150)/1000-11.25; Pset_CoveringCommon - FireRating: -; AcousticRating: -
Fliesen | WUN-H2-E03-009 | FLOORING | Fl1 0.15 m | 1266Bfl0812598640/01 | m² | Bodenbelagsarbeiten | 1 | 0.15 | 0 | 1 | Bodenfläche | Fl1 | 0 | 0 | NEW | AllplanAttributes - Bezeichnung: Fliesen; Raumnr. Bauherr: 2.11_A2_02; ash B_Aufbau: B10; ash B_Rutschhemmung: R10
Gipsfaserplatte | WUN-H2-E03-009 | CEILING | C/C 0.036 m | 1266Dfl0812721454/01 | m² | Trockenbauarbeiten | 1 | 0.036 | 0 | 1 | Deckenfläche | C/C | 0 | 0 | NEW | AllplanAttributes - Bezeichnung: Gipsfaserplatte
 | WUN-H2-E03-009 | CEILING | Installationshöhe 0 m | 1266Dfl0812608495/01 | m² | Trockenbauarbeiten | 1 | 0 | 0 | 1 | Bekleidung | Installationshöhe | 0 | 0 | NEW | 2.5 | Pset_CoveringCommon - FireRating: für korrekte FläVisu; AllplanAttributes - ash_lichte Raumhöhe: (13900-150)/1000-11.25
Rasterdecke | WUN-H2-E03-009 | CEILING | E3 0.15 m | 1266Dfl0812608495/02 | m² | Trockenbauarbeiten | 2 | 0.15 | 0 | 1 | Bekleidung | E3 | 0 | 0 | NEW | 2.5 | AllplanAttributes - Bezeichnung: Rasterdecke; ash_lichte Raumhöhe: (13900-150)/1000-11.25; Pset_CoveringCommon - FireRating: -; AcousticRating: -
Fliesen Mosaik | WUN-H2-E03-012a | FLOORING | Fl2 0.15 m | 1266Bfl0812715157/01 | m² | Bodenbelagsarbeiten | 1 | 0.15 | 0 | 1 | Bodenfläche | Fl2 | 0 | 0 | NEW | AllplanAttributes - Bezeichnung: Fliesen Mosaik; Raumnr. Bauherr: 2.11_A2_02; ash B_Aufbau: B11; ash B_Rutschhemmung: R10; ash B_Bewertungsgruppe Barfußbereich: B
Fliesen | WUN-H2-E03-012a | FLOORING | Fl1 0.15 m | 1266Bfl0000015502/01 | m² | Bodenbelagsarbeiten | 1 | 0.15 | 0 | 1 | Bodenfläche | Fl1 | 0 | 0 | NEW | AllplanAttributes - Bezeichnung: Fliesen; ash B_Aufbau: B10; ash B_Rutschhemmung: R10
Gipsfaserplatte | WUN-H2-E03-012a | CEILING | C/C 0.036 m | 1266Dfl0812721455/01 | m² | Trockenbauarbeiten | 1 | 0.036 | 0 | 1 | Deckenfläche | C/C | 0 | 0 | NEW | AllplanAttributes - Bezeichnung: Gipsfaserplatte
 | WUN-H2-E03-012a | CEILING | Installationshöhe 0 m | 1266Dfl0812611395/01 | m² | Trockenbauarbeiten | 1 | 0 | 0 | 1 | Bekleidung | Installationshöhe | 0 | 0 | NEW | 2.5 | Pset_CoveringCommon - FireRating: für korrekte FläVisu; AllplanAttributes - ash_lichte Raumhöhe: (13900-150)/1000-11.25
Rasterdecke | WUN-H2-E03-012a | CEILING | E3 0.15 m | 1266Dfl0812611395/02 | m² | Trockenbauarbeiten | 2 | 0.15 | 0 | 1 | Bekleidung | E3 | 0 | 0 | NEW | 2.5 | AllplanAttributes - Bezeichnung: Rasterdecke; ash_lichte Raumhöhe: (13900-150)/1000-11.25; Pset_CoveringCommon - FireRating: -; AcousticRating: -
PVC | WUN-H2-E03-012 | FLOORING | Ku3 0.15 m | 1266Bfl0000015489/01 | m² | Bodenbelagsarbeiten | 1 | 0.15 | 0 | 1 | Bodenfläche | Ku3 | 0 | 0 | NEW | AllplanAttributes - Bezeichnung: PVC; Raumnr. Bauherr: 2.11_A2_02; ash B_Aufbau: B9; ash B_Rutschhemmung: R9
Gipsfaserplatte | WUN-H2-E03-012 | CEILING | C/C 0.036 m | 1266Dfl0812721456/01 | m² | Trockenbauarbeiten | 1 | 0.036 | 0 | 1 | Deckenfläche | C/C | 0 | 0 | NEW | AllplanAttributes - Bezeichnung: Gipsfaserplatte
 | WUN-H2-E03-012 | CEILING | Installationshöhe 0 m | 1266Dfl0812647498/01 | m² | Trockenbauarbeiten | 1 | 0 | 0 | 1 | Bekleidung | Installationshöhe | 0 | 0 | NEW | 3.1 | Pset_CoveringCommon - FireRating: für korrekte FläVisu; AllplanAttributes - ash_lichte Raumhöhe: (14500-150)/1000-11.25; OKFF: 5.96
Rasterdecke | WUN-H2-E03-012 | CEILING | E3 0.15 m | 1266Dfl0812647498/02 | m² | Trockenbauarbeiten | 2 | 0.15 | 0 | 1 | Bekleidung | E3 | 0 | 0 | NEW | 3.1 | AllplanAttributes - Bezeichnung: Rasterdecke; ash_lichte Raumhöhe: (14500-150)/1000-11.25; Pset_CoveringCommon - FireRating: -; AcousticRating: -
 | WUN-H2-E03-012 | CEILING | Installationshöhe 0 m | 1266Dfl0812667738/01 | m² | Trockenbauarbeiten | 1 | 0 | 0 | 1 | Bekleidung | Installationshöhe | 0 | 0 | NEW | 2.5 | Pset_CoveringCommon - FireRating: für korrekte FläVisu; AllplanAttributes - ash_lichte Raumhöhe: (13900-150)/1000-11.25; OKFF: 5.96
Rasterdecke | WUN-H2-E03-012 | CEILING | E3 0.15 m | 1266Dfl0812667738/02 | m² | Trockenbauarbeiten | 2 | 0.15 | 0 | 1 | Bekleidung | E3 | 0 | 0 | NEW | 2.5 | AllplanAttributes - Bezeichnung: Rasterdecke; ash_lichte Raumhöhe: (13900-150)/1000-11.25; Pset_CoveringCommon - FireRating: -; AcousticRating: -
PVC | WUN-H2-E03-003 | FLOORING | Ku3 0.15 m | 1266Bfl0000012809/01 | m² | Bodenbelagsarbeiten | 1 | 0.15 | 0 | 1 | Bodenfläche | Ku3 | 0 | 0 | NEW | AllplanAttributes - Bezeichnung: PVC; Raumnr. Bauherr: 2.11_A2_02; ash B_Aufbau: B9; ash B_Rutschhemmung: R9
Gipsfaserplatte | WUN-H2-E03-003 | CEILING | C/C 0.036 m | 1266Dfl0812721457/01 | m² | Trockenbauarbeiten | 1 | 0.036 | 0 | 1 | Deckenfläche | C/C | 0 | 0 | NEW | AllplanAttributes - Bezeichnung: Gipsfaserplatte
 | WUN-H2-E03-003 | CEILING | Installationshöhe 0 m | 1266Dfl0812604144/01 | m² | Trockenbauarbeiten | 1 | 0 | 0 | 1 | Bekleidung | Installationshöhe | 0 | 0 | NEW | 2.5 | Pset_CoveringCommon - FireRating: für korrekte FläVisu; AllplanAttributes - ash_lichte Raumhöhe: (13900-150)/1000-11.25
Rasterdecke | WUN-H2-E03-003 | CEILING | E3 0.15 m | 1266Dfl0812604144/02 | m² | Trockenbauarbeiten | 2 | 0.15 | 0 | 1 | Bekleidung | E3 | 0 | 0 | NEW | 2.5 | AllplanAttributes - Bezeichnung: Rasterdecke; ash_lichte Raumhöhe: (13900-150)/1000-11.25; Pset_CoveringCommon - FireRating: -; AcousticRating: -
 | WUN-H2-E03-003 | CEILING | Installationshöhe 0 m | 1266Dfl0812686034/01 | m² | Trockenbauarbeiten | 1 | 0 | 0 | 1 | Bekleidung | Installationshöhe | 0 | 0 | NEW | 2.5 | Pset_CoveringCommon - FireRating: für korrekte FläVisu; AllplanAttributes - ash_lichte Raumhöhe: 2.500000
 | WUN-H2-E03-003 | CEILING | A1 0.15 m | 1266Dfl0812686034/02 | m² | Trockenbauarbeiten | 2 | 0.15 | 0 | 1 | Bekleidung | A1 | 0 | 0 | NEW | 2.5 | Pset_CoveringCommon - FireRating: -; AcousticRating: -; AllplanAttributes - ash_lichte Raumhöhe: 2.500000
 | WUN-H2-E03-003 | CEILING | D1 0.001 m | 1266Dfl0812686034/03 | m² | Maler- und Lackierarbeiten | 3 | 0.001 | 0 | 1 | Bekleidung | D1 | 0 | 0 | NEW | 2.5 | AllplanAttributes - ash_lichte Raumhöhe: 2.500000; OKFF: 0
Beschichtung wasserfest | WUN-H2-E03-019 | FLOORING | Bw 0.15 m | 1266Bfl0000015373/01 | m² | Bodenbelagsarbeiten | 1 | 0.15 | 0 | 1 | Bodenfläche | Bw | 0 | 0 | NEW | AllplanAttributes - Bezeichnung: Beschichtung wasserfest; Raumnr. Bauherr: 2.11_A2_02; ash B_Aufbau: B12; ash B_Rutschhemmung: R10
Gipsfaserplatte | WUN-H2-E03-019 | CEILING | C/C 0.036 m | 1266Dfl0812721458/01 | m² | Trockenbauarbeiten | 1 | 0.036 | 0 | 1 | Deckenfläche | C/C | 0 | 0 | NEW | AllplanAttributes - Bezeichnung: Gipsfaserplatte
 | WUN-H2-E03-019 | CEILING | Installationshöhe 0 m | 1266Dfl0812612555/01 | m² | Trockenbauarbeiten | 1 | 0 | 0 | 1 | Bekleidung | Installationshöhe | 0 | 0 | NEW | 2.5 | Pset_CoveringCommon - FireRating: für korrekte FläVisu; AllplanAttributes - ash_lichte Raumhöhe: (13900-150)/1000-11.25
Rasterdecke | WUN-H2-E03-019 | CEILING | E3 0.15 m | 1266Dfl0812612555/02 | m² | Trockenbauarbeiten | 2 | 0.15 | 0 | 1 | Bekleidung | E3 | 0 | 0 | NEW | 2.5 | AllplanAttributes - Bezeichnung: Rasterdecke; ash_lichte Raumhöhe: (13900-150)/1000-11.25; Pset_CoveringCommon - FireRating: -; AcousticRating: -
Beschichtung ölfest | WUN-H2-E03-015 | FLOORING | Bö 0.15 m | 1266Bfl0812724248/01 | m² | Bodenbelagsarbeiten | 1 | 0.15 | 0 | 1 | Bodenfläche | Bö | 0 | 0 | NEW | AllplanAttributes - Bezeichnung: Beschichtung ölfest; Raumnr. Bauherr: 2.11_A2_02; ash B_Aufbau: B12; ash B_Rutschhemmung: R10
Gipsfaserplatte | WUN-H2-E03-015 | CEILING | C/C 0.036 m | 1266Dfl0000012915/01 | m² | Trockenbauarbeiten | 1 | 0.036 | 0 | 1 | Deckenfläche | C/C | 0 | 0 | NEW | AllplanAttributes - Bezeichnung: Gipsfaserplatte
Gipsfaserplatte | WUN-H2-E03-015 | CEILING | D4 0.001 m | 1266Dfl0000012915/02 | m² | Maler- und Lackierarbeiten | 2 | 0.001 | 0 | 1 | Bekleidung | D4 | 0 | 0 | NEW | 3.324 | AllplanAttributes - ash_lichte Raumhöhe: 3.158729; OKFF: 5.11
Beschichtung ölfest | WUN-H2-E03-005 | FLOORING | Bö 0.15 m | 1266Bfl0812725295/01 | m² | Bodenbelagsarbeiten | 1 | 0.15 | 0 | 1 | Bodenfläche | Bö | 0 | 0 | NEW | AllplanAttributes - Bezeichnung: Beschichtung ölfest; Raumnr. Bauherr: 2.11_A2_02; ash B_Aufbau: B12; ash B_Rutschhemmung: R10
Gipsfaserplatte | WUN-H2-E03-005 | CEILING | C/C 0.036 m | 1266Dfl0000012790/01 | m² | Trockenbauarbeiten | 1 | 0.036 | 0 | 1 | Deckenfläche | C/C | 0 | 0 | NEW | AllplanAttributes - Bezeichnung: Gipsfaserplatte
Gipsfaserplatte | WUN-H2-E03-005 | CEILING | D4 0.001 m | 1266Dfl0000012790/02 | m² | Maler- und Lackierarbeiten | 2 | 0.001 | 0 | 1 | Bekleidung | D4 | 0 | 0 | NEW | 3.324 | AllplanAttributes - ash_lichte Raumhöhe: 3.343054; OKFF: 5.11
Feinsteinzeugplatten 40x40x3 | WUN-H2-E03- | FLOORING | FP2 0.28 m | 1266Bfl0812715357/01 | m² | Bodenbelagsarbeiten | 1 | 0.28 | 0 | 1 | Bodenfläche | FP2 | 0 | 0 | NEW | AllplanAttributes - Bezeichnung: Feinsteinzeugplatten 40x40x3
Handlauf | H2 Ebene +2 | CLADDING | 97 0.001 m | 1215Sfl0000081961/02 | m² | Maler- und Lackierarbeiten | 2 | 0.001 | 0 | 1 | Seitenfläche | 97 | 0 | 0 | NEW | AllplanAttributes - Bezeichnung: Handlauf
a-sh Abschluss Abhangdecke | H2 Ebene +2 | CEILING |  | 1215HWa0000152027 | m² |  |  |  |  |  | Gesamtwand |  |  |  | NEW | AllplanAttributes - Bezeichnung: a-sh Abschluss Abhangdecke; Attributset-Objekt: Covering; Object Layer Attributes #1, 2D Interaktion: yes; Object Layer Attributes #1, Gewerk: Trockenbauarbeiten; Object Layer Attributes #1, Material: A; Object Layer Attributes #1, Attributset-Objekt: Covering; Object Layer Attributes #1, Allright_Bauteil_ID: 1215Wa 0000152028; Object Layer Attributes #1, Abrechnungsart: m²; Object Layer Attributes #1, Objektname: Wand; Pset_CoveringCommon - IsExternal: no; FireRating: -; ThermalTransmittance: 0 W/K/m2; Reference: Reference
a-sh Abschluss Abhangdecke | H2 Ebene +2 | CEILING |  | 1215HWa0000152032 | m² |  |  |  |  |  | Gesamtwand |  |  |  | NEW | AllplanAttributes - Bezeichnung: a-sh Abschluss Abhangdecke; Attributset-Objekt: Covering; Object Layer Attributes #1, 2D Interaktion: yes; Object Layer Attributes #1, Gewerk: Trockenbauarbeiten; Object Layer Attributes #1, Material: A; Object Layer Attributes #1, Attributset-Objekt: Covering; Object Layer Attributes #1, Allright_Bauteil_ID: 1215Wa 0000152033; Object Layer Attributes #1, Abrechnungsart: m²; Object Layer Attributes #1, Objektname: Wand; Pset_CoveringCommon - IsExternal: no; FireRating: -; ThermalTransmittance: 0 W/K/m2; Reference: Reference
a-sh Abschluss Abhangdecke | H2 Ebene +2 | CEILING |  | 1215HWa0000152037 | m² |  |  |  |  |  | Gesamtwand |  |  |  | NEW | AllplanAttributes - Bezeichnung: a-sh Abschluss Abhangdecke; Attributset-Objekt: Covering; Object Layer Attributes #1, 2D Interaktion: yes; Object Layer Attributes #1, Gewerk: Trockenbauarbeiten; Object Layer Attributes #1, Material: A; Object Layer Attributes #1, Attributset-Objekt: Covering; Object Layer Attributes #1, Allright_Bauteil_ID: 1215Wa 0000152038; Object Layer Attributes #1, Abrechnungsart: m²; Object Layer Attributes #1, Objektname: Wand; Pset_CoveringCommon - IsExternal: no; FireRating: -; ThermalTransmittance: 0 W/K/m2; Reference: Reference
a-sh Abschluss Abhangdecke | H2 Ebene +2 | CEILING |  | 1215HWa0000152042 | m² |  |  |  |  |  | Gesamtwand |  |  |  | NEW | AllplanAttributes - Bezeichnung: a-sh Abschluss Abhangdecke; Attributset-Objekt: Covering; Object Layer Attributes #1, 2D Interaktion: yes; Object Layer Attributes #1, Gewerk: Trockenbauarbeiten; Object Layer Attributes #1, Material: A; Object Layer Attributes #1, Attributset-Objekt: Covering; Object Layer Attributes #1, Allright_Bauteil_ID: 1215Wa 0000152043; Object Layer Attributes #1, Abrechnungsart: m²; Object Layer Attributes #1, Objektname: Wand; Pset_CoveringCommon - IsExternal: no; FireRating: -; ThermalTransmittance: 0 W/K/m2; Reference: Reference
a-sh Abschluss Abhangdecke | H2 Ebene +2 | CEILING |  | 1215HWa0000158987 | m² |  |  |  |  |  | Gesamtwand |  |  |  | NEW | AllplanAttributes - Bezeichnung: a-sh Abschluss Abhangdecke; Attributset-Objekt: Covering; Object Layer Attributes #1, 2D Interaktion: yes; Object Layer Attributes #1, Gewerk: Trockenbauarbeiten; Object Layer Attributes #1, Material: A; Object Layer Attributes #1, Attributset-Objekt: Covering; Object Layer Attributes #1, Allright_Bauteil_ID: 1215Wa 0000158993; Object Layer Attributes #1, Abrechnungsart: m²; Object Layer Attributes #1, Objektname: Wand; Object Layer Attributes #1, Bezeichnung: a-sh Abschluss Abhangdecke; Pset_CoveringCommon - IsExternal: no; FireRating: -; ThermalTransmittance: 0 W/K/m2; Reference: Reference
a-sh Abschluss Abhangdecke | H2 Ebene +2 | CEILING |  | 1215HWa0000158986 | m² |  |  |  |  |  | Gesamtwand |  |  |  | NEW | AllplanAttributes - Bezeichnung: a-sh Abschluss Abhangdecke; Attributset-Objekt: Covering; Object Layer Attributes #1, 2D Interaktion: yes; Object Layer Attributes #1, Gewerk: Trockenbauarbeiten; Object Layer Attributes #1, Material: A; Object Layer Attributes #1, Attributset-Objekt: Covering; Object Layer Attributes #1, Allright_Bauteil_ID: 1215Wa 0000158991; Object Layer Attributes #1, Abrechnungsart: m²; Object Layer Attributes #1, Objektname: Wand; Object Layer Attributes #1, Bezeichnung: a-sh Abschluss Abhangdecke; Pset_CoveringCommon - IsExternal: no; FireRating: -; ThermalTransmittance: 0 W/K/m2; Reference: Reference
a-sh Abschluss Abhangdecke | H2 Ebene +2 | CEILING |  | 1215HWa0000158995 | m² |  |  |  |  |  | Gesamtwand |  |  |  | NEW | AllplanAttributes - Bezeichnung: a-sh Abschluss Abhangdecke; Attributset-Objekt: Covering; Object Layer Attributes #1, 2D Interaktion: yes; Object Layer Attributes #1, Gewerk: Trockenbauarbeiten; Object Layer Attributes #1, Material: A; Object Layer Attributes #1, Attributset-Objekt: Covering; Object Layer Attributes #1, Allright_Bauteil_ID: 1215Wa 0000159001; Object Layer Attributes #1, Abrechnungsart: m²; Object Layer Attributes #1, Objektname: Wand; Object Layer Attributes #1, Bezeichnung: a-sh Abschluss Abhangdecke; Pset_CoveringCommon - IsExternal: no; FireRating: -; ThermalTransmittance: 0 W/K/m2; Reference: Reference
a-sh Abschluss Abhangdecke | H2 Ebene +2 | CEILING |  | 1215HWa0000158994 | m² |  |  |  |  |  | Gesamtwand |  |  |  | NEW | AllplanAttributes - Bezeichnung: a-sh Abschluss Abhangdecke; Attributset-Objekt: Covering; Object Layer Attributes #1, 2D Interaktion: yes; Object Layer Attributes #1, Gewerk: Trockenbauarbeiten; Object Layer Attributes #1, Material: A; Object Layer Attributes #1, Attributset-Objekt: Covering; Object Layer Attributes #1, Allright_Bauteil_ID: 1215Wa 0000158999; Object Layer Attributes #1, Abrechnungsart: m²; Object Layer Attributes #1, Objektname: Wand; Object Layer Attributes #1, Bezeichnung: a-sh Abschluss Abhangdecke; Pset_CoveringCommon - IsExternal: no; FireRating: -; ThermalTransmittance: 0 W/K/m2; Reference: Reference
a-sh Abschluss Abhangdecke | H2 Ebene +2 | CEILING |  | 1215HWa0000159003 | m² |  |  |  |  |  | Gesamtwand |  |  |  | NEW | AllplanAttributes - Bezeichnung: a-sh Abschluss Abhangdecke; Attributset-Objekt: Covering; Object Layer Attributes #1, 2D Interaktion: yes; Object Layer Attributes #1, Gewerk: Trockenbauarbeiten; Object Layer Attributes #1, Material: A; Object Layer Attributes #1, Attributset-Objekt: Covering; Object Layer Attributes #1, Allright_Bauteil_ID: 1215Wa 0000159009; Object Layer Attributes #1, Abrechnungsart: m²; Object Layer Attributes #1, Objektname: Wand; Object Layer Attributes #1, Bezeichnung: a-sh Abschluss Abhangdecke; Pset_CoveringCommon - IsExternal: no; FireRating: -; ThermalTransmittance: 0 W/K/m2; Reference: Reference
a-sh Abschluss Abhangdecke | H2 Ebene +2 | CEILING |  | 1215HWa0000159002 | m² |  |  |  |  |  | Gesamtwand |  |  |  | NEW | AllplanAttributes - Bezeichnung: a-sh Abschluss Abhangdecke; Attributset-Objekt: Covering; Object Layer Attributes #1, 2D Interaktion: yes; Object Layer Attributes #1, Gewerk: Trockenbauarbeiten; Object Layer Attributes #1, Material: A; Object Layer Attributes #1, Attributset-Objekt: Covering; Object Layer Attributes #1, Allright_Bauteil_ID: 1215Wa 0000159007; Object Layer Attributes #1, Abrechnungsart: m²; Object Layer Attributes #1, Objektname: Wand; Object Layer Attributes #1, Bezeichnung: a-sh Abschluss Abhangdecke; Pset_CoveringCommon - IsExternal: no; FireRating: -; ThermalTransmittance: 0 W/K/m2; Reference: Reference
a-sh Abschluss Abhangdecke | H2 Ebene +2 | CEILING |  | 1215HWa0000159011 | m² |  |  |  |  |  | Gesamtwand |  |  |  | NEW | AllplanAttributes - Bezeichnung: a-sh Abschluss Abhangdecke; Attributset-Objekt: Covering; Object Layer Attributes #1, 2D Interaktion: yes; Object Layer Attributes #1, Gewerk: Trockenbauarbeiten; Object Layer Attributes #1, Material: A; Object Layer Attributes #1, Attributset-Objekt: Covering; Object Layer Attributes #1, Allright_Bauteil_ID: 1215Wa 0000159017; Object Layer Attributes #1, Abrechnungsart: m²; Object Layer Attributes #1, Objektname: Wand; Object Layer Attributes #1, Bezeichnung: a-sh Abschluss Abhangdecke; Pset_CoveringCommon - IsExternal: no; FireRating: -; ThermalTransmittance: 0 W/K/m2; Reference: Reference
a-sh Abschluss Abhangdecke | H2 Ebene +2 | CEILING |  | 1215HWa0000159010 | m² |  |  |  |  |  | Gesamtwand |  |  |  | NEW | AllplanAttributes - Bezeichnung: a-sh Abschluss Abhangdecke; Attributset-Objekt: Covering; Object Layer Attributes #1, 2D Interaktion: yes; Object Layer Attributes #1, Gewerk: Trockenbauarbeiten; Object Layer Attributes #1, Material: A; Object Layer Attributes #1, Attributset-Objekt: Covering; Object Layer Attributes #1, Allright_Bauteil_ID: 1215Wa 0000159015; Object Layer Attributes #1, Abrechnungsart: m²; Object Layer Attributes #1, Objektname: Wand; Object Layer Attributes #1, Bezeichnung: a-sh Abschluss Abhangdecke; Pset_CoveringCommon - IsExternal: no; FireRating: -; ThermalTransmittance: 0 W/K/m2; Reference: Reference
a-sh Abschluss Abhangdecke | H2 Ebene +2 | CEILING |  | 1215HWa0000162412 | m² |  |  |  |  |  | Gesamtwand |  |  |  | NEW | AllplanAttributes - Bezeichnung: a-sh Abschluss Abhangdecke; Attributset-Objekt: Covering; Object Layer Attributes #1, 2D Interaktion: yes; Object Layer Attributes #1, Gewerk: Trockenbauarbeiten; Object Layer Attributes #1, Material: A; Object Layer Attributes #1, Attributset-Objekt: Covering; Object Layer Attributes #1, Allright_Bauteil_ID: 1215Wa 0000162415; Object Layer Attributes #1, Abrechnungsart: m²; Object Layer Attributes #1, Objektname: Wand; Object Layer Attributes #1, Bezeichnung: a-sh Abschluss Abhangdecke; Pset_CoveringCommon - IsExternal: no; FireRating: -; ThermalTransmittance: 0 W/K/m2; Reference: Reference
Rasterdecke | H2 Ebene +2 | CEILING | E3 0.1 m | 1215Dfl0000153532/01 | m² | Trockenbauarbeiten | 1 | 0.1 | 0 | 1 | Bekleidung | E3 | 0 | 0 | NEW | 2.5 | AllplanAttributes - Bezeichnung: Rasterdecke; ash_lichte Raumhöhe: 2.5; Pset_CoveringCommon - AcousticRating: -
Gipsfaserplatten 2-lagig (BSK) | H2 Ebene +2 | CEILING | layer 0.036 m | 1215Dfl0000100910/01 | m² | Trockenbauarbeiten | 1 | 0.036 | 0 | 1 | Deckenfläche |  | 0 | 0 | NEW | 2.5 | AllplanAttributes - Bezeichnung: Gipsfaserplatten 2-lagig (BSK); ash_lichte Raumhöhe: 10.04
 | H2 Ebene +2 | CEILING | Installationshöhe 0.674 m | 1215Dfl0000100910/02 | m² | Trockenbauarbeiten | 2 | 0.674 | 0 | 1 | Bekleidung | Installationshöhe | 0 | 0 | NEW
 | H2 Ebene +2 | CEILING | A1 0.15 m | 1215Dfl0000100910/03 | m² | Trockenbauarbeiten | 3 | 0.15 | 0 | 1 | Bekleidung | A1 | 0 | 0 | NEW | Pset_CoveringCommon - AcousticRating: -
 | H2 Ebene +2 | CEILING | D1 0.001 m | 1215Dfl0000100910/04 | m² | Maler- und Lackierarbeiten | 4 | 0.001 | 0 | 1 | Bekleidung | D1 | 0 | 0 | NEW
Gipsfaserplatten 2-lagig (BSK) | H2 Ebene +2 | CEILING | layer 0.036 m | 1215Dfl0000101235/01 | m² | Trockenbauarbeiten | 1 | 0.036 | 0 | 1 | Deckenfläche |  | 0 | 0 | NEW | 2.5 | AllplanAttributes - Bezeichnung: Gipsfaserplatten 2-lagig (BSK); ash_lichte Raumhöhe: 2.5
 | H2 Ebene +2 | CEILING | Installationshöhe 0.714 m | 1215Dfl0000101235/02 | m² | Trockenbauarbeiten | 2 | 0.714 | 0 | 1 | Bekleidung | Installationshöhe | 0 | 0 | NEW
 | H2 Ebene +2 | CEILING | A1 0.15 m | 1215Dfl0000101235/03 | m² | Trockenbauarbeiten | 3 | 0.15 | 0 | 1 | Bekleidung | A1 | 0 | 0 | NEW | Pset_CoveringCommon - AcousticRating: -
 | H2 Ebene +2 | CEILING | D1 0.001 m | 1215Dfl0000101235/04 | m² | Maler- und Lackierarbeiten | 4 | 0.001 | 0 | 1 | Bekleidung | D1 | 0 | 0 | NEW
Gipsfaserplatten 2-lagig (BSK) | H2 Ebene +2 | CEILING | layer 0.036 m | 1215Dfl0000101248/01 | m² | Trockenbauarbeiten | 1 | 0.036 | 0 | 1 | Deckenfläche |  | 0 | 0 | NEW | 2.5 | AllplanAttributes - Bezeichnung: Gipsfaserplatten 2-lagig (BSK); ash_lichte Raumhöhe: -1.25
 | H2 Ebene +2 | CEILING | Installationshöhe 0.714 m | 1215Dfl0000101248/02 | m² | Trockenbauarbeiten | 2 | 0.714 | 0 | 1 | Bekleidung | Installationshöhe | 0 | 0 | NEW
 | H2 Ebene +2 | CEILING | A1 0.15 m | 1215Dfl0000101248/03 | m² | Trockenbauarbeiten | 3 | 0.15 | 0 | 1 | Bekleidung | A1 | 0 | 0 | NEW | Pset_CoveringCommon - AcousticRating: -
 | H2 Ebene +2 | CEILING | D1 0.001 m | 1215Dfl0000101248/04 | m² | Maler- und Lackierarbeiten | 4 | 0.001 | 0 | 1 | Bekleidung | D1 | 0 | 0 | NEW
PVC Bahnenware Holzoptik | WUN-H2-E02-F03 | FLOORING | Ku1 0.15 m | 1215Bfl0000116276/01 | m² | Bodenbelagsarbeiten | 1 | 0.15 | 0 | 1 | Bodenfläche | Ku1 | 0 | 0 | NEW | AllplanAttributes - Bezeichnung: PVC Bahnenware Holzoptik; Raumnr. Bauherr: 2.11_A2_02; ash B_Aufbau: B9; ash B_Rutschhemmung: R9
Handlauf | WUN-H2-E02-F03 | CLADDING | 97 0.001 m | 1215Sfl0000081776/02 | m² | Maler- und Lackierarbeiten | 2 | 0.001 | 0 | 1 | Seitenfläche | 97 | 0 | 0 | NEW | AllplanAttributes - Bezeichnung: Handlauf
Acrovyn | WUN-H2-E02-F03 | CLADDING | 84 0.001 m | 1215Sfl0000049327/02 | m² | Maler- und Lackierarbeiten | 2 | 0.001 | 0 | 1 | Seitenfläche | 84 | 0 | 0 | NEW | AllplanAttributes - Bezeichnung: Acrovyn
Handlauf | WUN-H2-E02-F03 | CLADDING | 97 0.001 m | 1215Sfl0000054856/02 | m² | Maler- und Lackierarbeiten | 2 | 0.001 | 0 | 1 | Seitenfläche | 97 | 0 | 0 | NEW | AllplanAttributes - Bezeichnung: Handlauf
Acrovyn | WUN-H2-E02-F03 | CLADDING | 84 0.001 m | 1215Sfl0000049036/02 | m² | Maler- und Lackierarbeiten | 2 | 0.001 | 0 | 1 | Seitenfläche | 84 | 0 | 0 | NEW | AllplanAttributes - Bezeichnung: Acrovyn
Gipsfaserplatten 2-lagig (BSK) | WUN-H2-E02-F03 | CEILING | layer 0.036 m | 1215Dfl0000099976/01 | m² | Trockenbauarbeiten | 1 | 0.036 | 0 | 1 | Deckenfläche |  | 0 | 0 | NEW | 2.5 | AllplanAttributes - Bezeichnung: Gipsfaserplatten 2-lagig (BSK); ash_lichte Raumhöhe: 2.54
 | WUN-H2-E02-F03 | CEILING | Installationshöhe 0.674 m | 1215Dfl0000099976/02 | m² | Trockenbauarbeiten | 2 | 0.674 | 0 | 1 | Bekleidung | Installationshöhe | 0 | 0 | NEW
 | WUN-H2-E02-F03 | CEILING | A1 0.15 m | 1215Dfl0000099976/03 | m² | Trockenbauarbeiten | 3 | 0.15 | 0 | 1 | Bekleidung | A1 | 0 | 0 | NEW | Pset_CoveringCommon - AcousticRating: -
 | WUN-H2-E02-F03 | CEILING | D1 0.001 m | 1215Dfl0000099976/04 | m² | Maler- und Lackierarbeiten | 4 | 0.001 | 0 | 1 | Bekleidung | D1 | 0 | 0 | NEW
Gipsfaserplatten 2-lagig (BSK) | WUN-H2-E02-F03 | CEILING | layer 0.036 m | 1215Dfl0000100272/01 | m² | Trockenbauarbeiten | 1 | 0.036 | 0 | 1 | Deckenfläche |  | 0 | 0 | NEW | 2.5 | AllplanAttributes - Bezeichnung: Gipsfaserplatten 2-lagig (BSK); ash_lichte Raumhöhe: 2.54
 | WUN-H2-E02-F03 | CEILING | Installationshöhe 0.674 m | 1215Dfl0000100272/02 | m² | Trockenbauarbeiten | 2 | 0.674 | 0 | 1 | Bekleidung | Installationshöhe | 0 | 0 | NEW
 | WUN-H2-E02-F03 | CEILING | A1 0.15 m | 1215Dfl0000100272/03 | m² | Trockenbauarbeiten | 3 | 0.15 | 0 | 1 | Bekleidung | A1 | 0 | 0 | NEW | Pset_CoveringCommon - AcousticRating: -
 | WUN-H2-E02-F03 | CEILING | D1 0.001 m | 1215Dfl0000100272/04 | m² | Maler- und Lackierarbeiten | 4 | 0.001 | 0 | 1 | Bekleidung | D1 | 0 | 0 | NEW
Gipsfaserplatten 2-lagig (BSK) | WUN-H2-E02-F03 | CEILING | layer 0.036 m | 1215Dfl0000099680/01 | m² | Trockenbauarbeiten | 1 | 0.036 | 0 | 1 | Deckenfläche |  | 0 | 0 | NEW | 2.5 | AllplanAttributes - Bezeichnung: Gipsfaserplatten 2-lagig (BSK); ash_lichte Raumhöhe: 2.5
 | WUN-H2-E02-F03 | CEILING | Installationshöhe 0.714 m | 1215Dfl0000099680/02 | m² | Trockenbauarbeiten | 2 | 0.714 | 0 | 1 | Bekleidung | Installationshöhe | 0 | 0 | NEW
 | WUN-H2-E02-F03 | CEILING | Aa 0.15 m | 1215Dfl0000099680/03 | m² | Trockenbauarbeiten | 3 | 0.15 | 0 | 1 | Bekleidung | Aa | 0 | 0 | NEW | Pset_CoveringCommon - AcousticRating: -
 | WUN-H2-E02-F03 | CEILING | D1 0.001 m | 1215Dfl0000099680/04 | m² | Maler- und Lackierarbeiten | 4 | 0.001 | 0 | 1 | Bekleidung | D1 | 0 | 0 | NEW
Gipsfaserplatten 2-lagig (BSK) | WUN-H2-E02-F03 | CEILING | layer 0.036 m | 1215Dfl0000006821/01 | m² | Trockenbauarbeiten | 1 | 0.036 | 0 | 1 | Deckenfläche |  | 0 | 0 | NEW | 3.15 | AllplanAttributes - Bezeichnung: Gipsfaserplatten 2-lagig (BSK); ash_lichte Raumhöhe: 3.1
 | WUN-H2-E02-F03 | CEILING | Installationshöhe 0.164 m | 1215Dfl0000006821/02 | m² | Trockenbauarbeiten | 2 | 0.164 | 0 | 1 | Bekleidung | Installationshöhe | 0 | 0 | NEW | Pset_CoveringCommon - AcousticRating: -
 | WUN-H2-E02-F03 | CEILING | A1 0.1 m | 1215Dfl0000006821/03 | m² | Trockenbauarbeiten | 3 | 0.1 | 0 | 1 | Bekleidung | A1 | 0 | 0 | NEW | Pset_CoveringCommon - AcousticRating: -
 | WUN-H2-E02-F03 | CEILING | D1 0.001 m | 1215Dfl0000006821/04 | m² | Maler- und Lackierarbeiten | 4 | 0.001 | 0 | 1 | Bekleidung | D1 | 0 | 0 | NEW
Gipsfaserplatten 2-lagig (BSK) | WUN-H2-E02-F03 | CEILING | layer 0.036 m | 1215Dfl0000008616/01 | m² | Trockenbauarbeiten | 1 | 0.036 | 0 | 1 | Deckenfläche |  | 0 | 0 | NEW | 2.5 | AllplanAttributes - Bezeichnung: Gipsfaserplatten 2-lagig (BSK); ash_lichte Raumhöhe: 2.5
 | WUN-H2-E02-F03 | CEILING | Installationshöhe 0.714 m | 1215Dfl0000008616/02 | m² | Trockenbauarbeiten | 2 | 0.714 | 0 | 1 | Bekleidung | Installationshöhe | 0 | 0 | NEW
 | WUN-H2-E02-F03 | CEILING | A1 0.15 m | 1215Dfl0000008616/03 | m² | Trockenbauarbeiten | 3 | 0.15 | 0 | 1 | Bekleidung | A1 | 0 | 0 | NEW | Pset_CoveringCommon - AcousticRating: -
 | WUN-H2-E02-F03 | CEILING | D1 0.001 m | 1215Dfl0000008616/04 | m² | Maler- und Lackierarbeiten | 4 | 0.001 | 0 | 1 | Bekleidung | D1 | 0 | 0 | NEW
PVC Bahnenware Holzoptik | WUN-H2-E02-F07 | FLOORING | Ku1 0.15 m | 1215Bfl0000006818/01 | m² | Bodenbelagsarbeiten | 1 | 0.15 | 0 | 1 | Bodenfläche | Ku1 | 0 | 0 | NEW | AllplanAttributes - Bezeichnung: PVC Bahnenware Holzoptik; Raumnr. Bauherr: 2.11_A2_02; ash B_Aufbau: B9; ash B_Rutschhemmung: R9
Handlauf | WUN-H2-E02-F07 | CLADDING | 97 0.001 m | 1215Sfl0000081599/02 | m² | Maler- und Lackierarbeiten | 2 | 0.001 | 0 | 1 | Seitenfläche | 97 | 0 | 0 | NEW | AllplanAttributes - Bezeichnung: Handlauf
Handlauf | WUN-H2-E02-F07 | CLADDING | 97 0.001 m | 1215Sfl0000053983/02 | m² | Maler- und Lackierarbeiten | 2 | 0.001 | 0 | 1 | Seitenfläche | 97 | 0 | 0 | NEW | AllplanAttributes - Bezeichnung: Handlauf
Handlauf | WUN-H2-E02-F07 | CLADDING | 97 0.001 m | 1215Sfl0000053692/02 | m² | Maler- und Lackierarbeiten | 2 | 0.001 | 0 | 1 | Seitenfläche | 97 | 0 | 0 | NEW | AllplanAttributes - Bezeichnung: Handlauf
Gipsfaserplatten 2-lagig (BSK) | WUN-H2-E02-F07 | CEILING | layer 0.036 m | 1215Dfl0000062558/01 | m² | Trockenbauarbeiten | 1 | 0.036 | 0 | 1 | Deckenfläche |  | 0 | 0 | NEW | 2.5 | AllplanAttributes - Bezeichnung: Gipsfaserplatten 2-lagig (BSK); ash_lichte Raumhöhe: 2.5
 | WUN-H2-E02-F07 | CEILING | Installationshöhe 0.714 m | 1215Dfl0000062558/02 | m² | Trockenbauarbeiten | 2 | 0.714 | 0 | 1 | Bekleidung | Installationshöhe | 0 | 0 | NEW
 | WUN-H2-E02-F07 | CEILING | Aa 0.15 m | 1215Dfl0000062558/03 | m² | Trockenbauarbeiten | 3 | 0.15 | 0 | 1 | Bekleidung | Aa | 0 | 0 | NEW | Pset_CoveringCommon - AcousticRating: -
 | WUN-H2-E02-F07 | CEILING | D1 0.001 m | 1215Dfl0000062558/04 | m² | Maler- und Lackierarbeiten | 4 | 0.001 | 0 | 1 | Bekleidung | D1 | 0 | 0 | NEW
Gipsfaserplatten 2-lagig (BSK) | WUN-H2-E02-F07 | CEILING | layer 0.036 m | 1215Dfl0000006817/01 | m² | Trockenbauarbeiten | 1 | 0.036 | 0 | 1 | Deckenfläche |  | 0 | 0 | NEW | 3.15 | AllplanAttributes - Bezeichnung: Gipsfaserplatten 2-lagig (BSK); ash_lichte Raumhöhe: 3.1
 | WUN-H2-E02-F07 | CEILING | Installationshöhe 0.164 m | 1215Dfl0000006817/02 | m² | Trockenbauarbeiten | 2 | 0.164 | 0 | 1 | Bekleidung | Installationshöhe | 0 | 0 | NEW | Pset_CoveringCommon - AcousticRating: -
 | WUN-H2-E02-F07 | CEILING | A1 0.1 m | 1215Dfl0000006817/03 | m² | Trockenbauarbeiten | 3 | 0.1 | 0 | 1 | Bekleidung | A1 | 0 | 0 | NEW | Pset_CoveringCommon - AcousticRating: -
 | WUN-H2-E02-F07 | CEILING | D1 0.001 m | 1215Dfl0000006817/04 | m² | Maler- und Lackierarbeiten | 4 | 0.001 | 0 | 1 | Bekleidung | D1 | 0 | 0 | NEW
Gipsfaserplatten 2-lagig (BSK) | WUN-H2-E02-F07 | CEILING | layer 0.036 m | 1215Dfl0000008907/01 | m² | Trockenbauarbeiten | 1 | 0.036 | 0 | 1 | Deckenfläche |  | 0 | 0 | NEW | 2.5 | AllplanAttributes - Bezeichnung: Gipsfaserplatten 2-lagig (BSK); ash_lichte Raumhöhe: 2.5
 | WUN-H2-E02-F07 | CEILING | Installationshöhe 0.714 m | 1215Dfl0000008907/02 | m² | Trockenbauarbeiten | 2 | 0.714 | 0 | 1 | Bekleidung | Installationshöhe | 0 | 0 | NEW
 | WUN-H2-E02-F07 | CEILING | A1 0.15 m | 1215Dfl0000008907/03 | m² | Trockenbauarbeiten | 3 | 0.15 | 0 | 1 | Bekleidung | A1 | 0 | 0 | NEW | Pset_CoveringCommon - AcousticRating: -
 | WUN-H2-E02-F07 | CEILING | D1 0.001 m | 1215Dfl0000008907/04 | m² | Maler- und Lackierarbeiten | 4 | 0.001 | 0 | 1 | Bekleidung | D1 | 0 | 0 | NEW
Sichtbetonklasse SB3 | WUN-H2-E02-T01 | CLADDING | 03 0.001 m | 1215Sfl0000088484/02 | m² | Putz- und Stuckarbeiten | 2 | 0.001 | 0 | 1 | Seitenfläche | 03 | 0 | 0 | NEW | AllplanAttributes - Bezeichnung: Sichtbetonklasse SB3
Sichtbetonklasse SB3 | WUN-H2-E02-T01 | CLADDING | 47 0.001 m | 1215Sfl0000088484/04 | m² | Maler- und Lackierarbeiten | 4 | 0.001 | 0 | 1 | Seitenfläche | 47 | 0 | 0 | NEW
Fliesen Großformat | WUN-H2-E02-T01 | FLOORING | Fl12 0.15 m | 1215Bfl0000076658/01 | m² | Bodenbelagsarbeiten | 1 | 0.15 | 0 | 1 | Bodenfläche | Fl12 | 0 | 0 | NEW | AllplanAttributes - Bezeichnung: Fliesen Großformat; Raumnr. Bauherr: B8; ash B_Aufbau: B8; ash B_Rutschhemmung: R10
Fliesen Großformat | WUN-H2-E02-T01 | FLOORING | Fl12 0.06 m | 1215Bfl0000076773/01 | m² | Bodenbelagsarbeiten | 1 | 0.06 | 0 | 1 | Bodenfläche | Fl12 | 0 | 0 | NEW | AllplanAttributes - Bezeichnung: Fliesen Großformat; ash B_Aufbau: B6; ash B_Rutschhemmung: R10
Handlauf | WUN-H2-E02-T01 | CLADDING | 97 0.001 m | 1215Sfl0000058640/02 | m² | Maler- und Lackierarbeiten | 2 | 0.001 | 0 | 1 | Seitenfläche | 97 | 0 | 0 | NEW | AllplanAttributes - Bezeichnung: Handlauf
Gipsfaserplatten 2-lagig (BSK) | WUN-H2-E02-T01 | CEILING | layer 0.036 m | 1215Dfl0000076206/01 | m² | Trockenbauarbeiten | 1 | 0.036 | 0 | 1 | Deckenfläche |  | 0 | 0 | NEW | 2.75 | AllplanAttributes - Bezeichnung: Gipsfaserplatten 2-lagig (BSK); ash_lichte Raumhöhe: 2.75
 | WUN-H2-E02-T01 | CEILING | Installationshöhe 0.414 m | 1215Dfl0000076206/02 | m² | Trockenbauarbeiten | 2 | 0.414 | 0 | 1 | Bekleidung | Installationshöhe | 0 | 0 | NEW
 | WUN-H2-E02-T01 | CEILING | Aa 0.2 m | 1215Dfl0000076206/03 | m² | Trockenbauarbeiten | 3 | 0.2 | 0 | 1 | Bekleidung | Aa | 0 | 0 | NEW | Pset_CoveringCommon - FireRating: F60; AcousticRating: -
 | WUN-H2-E02-T01 | CEILING | D1 0.001 m | 1215Dfl0000076206/04 | m² | Maler- und Lackierarbeiten | 4 | 0.001 | 0 | 1 | Bekleidung | D1 | 0 | 0 | NEW
Gipsfaserplatten 2-lagig (BSK) | WUN-H2-E02-T01 | CEILING | layer 0.036 m | 1215Dfl0000076208/01 | m² | Trockenbauarbeiten | 1 | 0.036 | 0 | 1 | Deckenfläche |  | 0 | 0 | NEW | 2.75 | AllplanAttributes - Bezeichnung: Gipsfaserplatten 2-lagig (BSK); ash_lichte Raumhöhe: 2.75
 | WUN-H2-E02-T01 | CEILING | Installationshöhe 0.414 m | 1215Dfl0000076208/02 | m² | Trockenbauarbeiten | 2 | 0.414 | 0 | 1 | Bekleidung | Installationshöhe | 0 | 0 | NEW
 | WUN-H2-E02-T01 | CEILING | A1 0.2 m | 1215Dfl0000076208/03 | m² | Trockenbauarbeiten | 3 | 0.2 | 0 | 1 | Bekleidung | A1 | 0 | 0 | NEW | Pset_CoveringCommon - FireRating: F60; AcousticRating: -
 | WUN-H2-E02-T01 | CEILING | D1 0.001 m | 1215Dfl0000076208/04 | m² | Maler- und Lackierarbeiten | 4 | 0.001 | 0 | 1 | Bekleidung | D1 | 0 | 0 | NEW
Gipsfaserplatten 2-lagig (BSK) | WUN-H2-E02-T01 | CEILING | layer 0.036 m | 1215Dfl0000076209/01 | m² | Trockenbauarbeiten | 1 | 0.036 | 0 | 1 | Deckenfläche |  | 0 | 0 | NEW | 3.1 | AllplanAttributes - Bezeichnung: Gipsfaserplatten 2-lagig (BSK); ash_lichte Raumhöhe: 3.1
 | WUN-H2-E02-T01 | CEILING | Installationshöhe 0.164 m | 1215Dfl0000076209/02 | m² | Trockenbauarbeiten | 2 | 0.164 | 0 | 1 | Bekleidung | Installationshöhe | 0 | 0 | NEW
 | WUN-H2-E02-T01 | CEILING | A1 0.1 m | 1215Dfl0000076209/03 | m² | Trockenbauarbeiten | 3 | 0.1 | 0 | 1 | Bekleidung | A1 | 0 | 0 | NEW | Pset_CoveringCommon - FireRating: F60; AcousticRating: -
 | WUN-H2-E02-T01 | CEILING | D1 0.001 m | 1215Dfl0000076209/04 | m² | Maler- und Lackierarbeiten | 4 | 0.001 | 0 | 1 | Bekleidung | D1 | 0 | 0 | NEW
PVC Bahnenware Uni | WUN-H2-E02-F02 | FLOORING | Ku2 0.15 m | 1215Bfl0000006863/01 | m² | Bodenbelagsarbeiten | 1 | 0.15 | 0 | 1 | Bodenfläche | Ku2 | 0 | 0 | NEW | AllplanAttributes - Bezeichnung: PVC Bahnenware Uni; Raumnr. Bauherr: 2.11_A2_02; ash B_Aufbau: B9; ash B_Rutschhemmung: R9
Acrovyn | WUN-H2-E02-F02 | CLADDING | 84 0.001 m | 1215Sfl0000049909/02 | m² | Maler- und Lackierarbeiten | 2 | 0.001 | 0 | 1 | Seitenfläche | 84 | 0 | 0 | NEW | AllplanAttributes - Bezeichnung: Acrovyn
Gipsfaserplatten 2-lagig (BSK) | WUN-H2-E02-F02 | CEILING | layer 0.036 m | 1215Dfl0000006864/01 | m² | Trockenbauarbeiten | 1 | 0.036 | 0 | 1 | Deckenfläche |  | 0 | 0 | NEW | 3.15 | AllplanAttributes - Bezeichnung: Gipsfaserplatten 2-lagig (BSK); ash_lichte Raumhöhe: 3.1
 | WUN-H2-E02-F02 | CEILING | Installationshöhe 0.164 m | 1215Dfl0000006864/02 | m² | Trockenbauarbeiten | 2 | 0.164 | 0 | 1 | Bekleidung | Installationshöhe | 0 | 0 | NEW | Pset_CoveringCommon - AcousticRating: -
 | WUN-H2-E02-F02 | CEILING | A1 0.1 m | 1215Dfl0000006864/03 | m² | Trockenbauarbeiten | 3 | 0.1 | 0 | 1 | Bekleidung | A1 | 0 | 0 | NEW | Pset_CoveringCommon - FireRating: F60; AcousticRating: -
 | WUN-H2-E02-F02 | CEILING | D1 0.001 m | 1215Dfl0000006864/04 | m² | Maler- und Lackierarbeiten | 4 | 0.001 | 0 | 1 | Bekleidung | D1 | 0 | 0 | NEW
Gipsfaserplatten 2-lagig (BSK) | WUN-H2-E02-F02 | CEILING | layer 0.036 m | 1215Dfl0000009865/01 | m² | Trockenbauarbeiten | 1 | 0.036 | 0 | 1 | Deckenfläche |  | 0 | 0 | NEW | 2.65 | AllplanAttributes - Bezeichnung: Gipsfaserplatten 2-lagig (BSK); ash_lichte Raumhöhe: 2.65
 | WUN-H2-E02-F02 | CEILING | Installationshöhe 0.614 m | 1215Dfl0000009865/02 | m² | Trockenbauarbeiten | 2 | 0.614 | 0 | 1 | Bekleidung | Installationshöhe | 0 | 0 | NEW
 | WUN-H2-E02-F02 | CEILING | A1 0.1 m | 1215Dfl0000009865/03 | m² | Trockenbauarbeiten | 3 | 0.1 | 0 | 1 | Bekleidung | A1 | 0 | 0 | NEW | Pset_CoveringCommon - FireRating: F60; AcousticRating: -
 | WUN-H2-E02-F02 | CEILING | D1 0.001 m | 1215Dfl0000009865/04 | m² | Maler- und Lackierarbeiten | 4 | 0.001 | 0 | 1 | Bekleidung | D1 | 0 | 0 | NEW
PVC Bahnenware Holzoptik | WUN-H2-E02-F05 | FLOORING | Ku1 0.15 m | 1215Bfl0000006859/01 | m² | Bodenbelagsarbeiten | 1 | 0.15 | 0 | 1 | Bodenfläche | Ku1 | 0 | 0 | NEW | AllplanAttributes - Bezeichnung: PVC Bahnenware Holzoptik; Raumnr. Bauherr: 2.11_A2_02; ash B_Aufbau: B9; ash B_Rutschhemmung: R9
Handlauf | WUN-H2-E02-F05 | CLADDING | 97 0.001 m | 1215Sfl0000051073/02 | m² | Maler- und Lackierarbeiten | 2 | 0.001 | 0 | 1 | Seitenfläche | 97 | 0 | 0 | NEW | AllplanAttributes - Bezeichnung: Handlauf
Gipsfaserplatten 2-lagig (BSK) | WUN-H2-E02-F05 | CEILING | layer 0.036 m | 1215Dfl0000006860/01 | m² | Trockenbauarbeiten | 1 | 0.036 | 0 | 1 | Deckenfläche |  | 0 | 0 | NEW | 2.5 | AllplanAttributes - Bezeichnung: Gipsfaserplatten 2-lagig (BSK); ash_lichte Raumhöhe: 4.0352
 | WUN-H2-E02-F05 | CEILING | A1 0.1 m | 1215Dfl0000152245/01 | m² | Trockenbauarbeiten | 1 | 0.1 | 0 | 1 | Bekleidung | A1 | 0 | 0 | NEW | 2.5 | AllplanAttributes - ash_lichte Raumhöhe: 2.5; OKFF: 0; Pset_CoveringCommon - AcousticRating: -
 | WUN-H2-E02-F05 | CEILING | D1 0.001 m | 1215Dfl0000152245/02 | m² | Maler- und Lackierarbeiten | 2 | 0.001 | 0 | 1 | Bekleidung | D1 | 0 | 0 | NEW | AllplanAttributes - OKFF: 0
 | WUN-H2-E02-F05 | CEILING | Aa 0.1 m | 1215Dfl0000060131/01 | m² | Trockenbauarbeiten | 1 | 0.1 | 0 | 1 | Bekleidung | Aa | 0 | 0 | NEW | 2.5 | AllplanAttributes - ash_lichte Raumhöhe: 2.5; OKFF: 0; Pset_CoveringCommon - AcousticRating: -
 | WUN-H2-E02-F05 | CEILING | D1 0.001 m | 1215Dfl0000060131/02 | m² | Maler- und Lackierarbeiten | 2 | 0.001 | 0 | 1 | Bekleidung | D1 | 0 | 0 | NEW | AllplanAttributes - OKFF: 0
PVC Bahnenware Holzoptik | WUN-H2-E02-F06 | FLOORING | Ku1 0.15 m | 1215Bfl0000006853/01 | m² | Bodenbelagsarbeiten | 1 | 0.15 | 0 | 1 | Bodenfläche | Ku1 | 0 | 0 | NEW | AllplanAttributes - Bezeichnung: PVC Bahnenware Holzoptik; Raumnr. Bauherr: 2.11_A2_02; ash B_Aufbau: B9; ash B_Rutschhemmung: R9
Handlauf | WUN-H2-E02-F06 | CLADDING | 97 0.001 m | 1215Sfl0000050491/02 | m² | Maler- und Lackierarbeiten | 2 | 0.001 | 0 | 1 | Seitenfläche | 97 | 0 | 0 | NEW | AllplanAttributes - Bezeichnung: Handlauf
Handlauf | WUN-H2-E02-F06 | CLADDING | 97 0.001 m | 1215Sfl0000050782/02 | m² | Maler- und Lackierarbeiten | 2 | 0.001 | 0 | 1 | Seitenfläche | 97 | 0 | 0 | NEW | AllplanAttributes - Bezeichnung: Handlauf
Gipsfaserplatten 2-lagig (BSK) | WUN-H2-E02-F06 | CEILING | layer 0.036 m | 1215Dfl0000006854/01 | m² | Trockenbauarbeiten | 1 | 0.036 | 0 | 1 | Deckenfläche |  | 0 | 0 | NEW | 3.1 | AllplanAttributes - Bezeichnung: Gipsfaserplatten 2-lagig (BSK); ash_lichte Raumhöhe: 4.72951
 | WUN-H2-E02-F06 | CEILING | A1 0.1 m | 1215Dfl0000159019/01 | m² | Trockenbauarbeiten | 1 | 0.1 | 0 | 1 | Bekleidung | A1 | 0 | 0 | NEW | 2.5 | AllplanAttributes - ash_lichte Raumhöhe: 2.5; OKFF: 0; Pset_CoveringCommon - AcousticRating: -
 | WUN-H2-E02-F06 | CEILING | D1 0.001 m | 1215Dfl0000159019/02 | m² | Maler- und Lackierarbeiten | 2 | 0.001 | 0 | 1 | Bekleidung | D1 | 0 | 0 | NEW | AllplanAttributes - OKFF: 0
 | WUN-H2-E02-F06 | CEILING | Aa 0.1 m | 1215Dfl0000059551/01 | m² | Trockenbauarbeiten | 1 | 0.1 | 0 | 1 | Bekleidung | Aa | 0 | 0 | NEW | 2.5 | AllplanAttributes - ash_lichte Raumhöhe: 2.5; OKFF: 0; Pset_CoveringCommon - AcousticRating: -
 | WUN-H2-E02-F06 | CEILING | D1 0.001 m | 1215Dfl0000059551/02 | m² | Maler- und Lackierarbeiten | 2 | 0.001 | 0 | 1 | Bekleidung | D1 | 0 | 0 | NEW | AllplanAttributes - OKFF: 0
 | WUN-H2-E02-F06 | CEILING | A1 0.1 m | 1215Dfl0000007743/01 | m² | Trockenbauarbeiten | 1 | 0.1 | 0 | 1 | Bekleidung | A1 | 0 | 0 | NEW | 2.5 | AllplanAttributes - ash_lichte Raumhöhe: 2.5; OKFF: 0; Pset_CoveringCommon - AcousticRating: -
 | WUN-H2-E02-F06 | CEILING | D1 0.001 m | 1215Dfl0000007743/02 | m² | Maler- und Lackierarbeiten | 2 | 0.001 | 0 | 1 | Bekleidung | D1 | 0 | 0 | NEW | AllplanAttributes - OKFF: 0
 | WUN-H2-E02-F06 | CEILING | A1 0.1 m | 1215Dfl0000150049/01 | m² | Trockenbauarbeiten | 1 | 0.1 | 0 | 1 | Bekleidung | A1 | 0 | 0 | NEW | 2.5 | AllplanAttributes - ash_lichte Raumhöhe: 3.1; OKFF: 0; Pset_CoveringCommon - AcousticRating: -
 | WUN-H2-E02-F06 | CEILING | D1 0.001 m | 1215Dfl0000150049/02 | m² | Maler- und Lackierarbeiten | 2 | 0.001 | 0 | 1 | Bekleidung | D1 | 0 | 0 | NEW | AllplanAttributes - OKFF: 0
 | WUN-H2-E02-F06 | CEILING | Aa 0.1 m | 1215Dfl0000159166/01 | m² | Trockenbauarbeiten | 1 | 0.1 | 0 | 1 | Bekleidung | Aa | 0 | 0 | NEW | 2.5 | AllplanAttributes - ash_lichte Raumhöhe: 2.5; OKFF: 0; Pset_CoveringCommon - AcousticRating: -
 | WUN-H2-E02-F06 | CEILING | D1 0.001 m | 1215Dfl0000159166/02 | m² | Maler- und Lackierarbeiten | 2 | 0.001 | 0 | 1 | Bekleidung | D1 | 0 | 0 | NEW | AllplanAttributes - OKFF: 0
PVC Bahnenware Holzoptik | WUN-H2-E02-F04 | FLOORING | Ku1 0.15 m | 1215Bfl0000006867/01 | m² | Bodenbelagsarbeiten | 1 | 0.15 | 0 | 1 | Bodenfläche | Ku1 | 0 | 0 | NEW | AllplanAttributes - Bezeichnung: PVC Bahnenware Holzoptik; Raumnr. Bauherr: 2.11_A2_02; ash B_Aufbau: B9; ash B_Rutschhemmung: R9
Handlauf | WUN-H2-E02-F04 | CLADDING | 97 0.001 m | 1215Sfl0000051655/02 | m² | Maler- und Lackierarbeiten | 2 | 0.001 | 0 | 1 | Seitenfläche | 97 | 0 | 0 | NEW | AllplanAttributes - Bezeichnung: Handlauf
Handlauf | WUN-H2-E02-F04 | CLADDING | 97 0.001 m | 1215Sfl0000051946/02 | m² | Maler- und Lackierarbeiten | 2 | 0.001 | 0 | 1 | Seitenfläche | 97 | 0 | 0 | NEW | AllplanAttributes - Bezeichnung: Handlauf
Handlauf | WUN-H2-E02-F04 | CLADDING | 97 0.001 m | 1215Sfl0000051364/02 | m² | Maler- und Lackierarbeiten | 2 | 0.001 | 0 | 1 | Seitenfläche | 97 | 0 | 0 | NEW | AllplanAttributes - Bezeichnung: Handlauf
Gipsfaserplatten 2-lagig (BSK) | WUN-H2-E02-F04 | CEILING | layer 0.036 m | 1215Dfl0000006868/01 | m² | Trockenbauarbeiten | 1 | 0.036 | 0 | 1 | Deckenfläche |  | 0 | 0 | NEW | 3.1 | AllplanAttributes - Bezeichnung: Gipsfaserplatten 2-lagig (BSK); ash_lichte Raumhöhe: 4.75545
 | WUN-H2-E02-F04 | CEILING | Aa 0.1 m | 1215Dfl0000060716/01 | m² | Trockenbauarbeiten | 1 | 0.1 | 0 | 1 | Bekleidung | Aa | 0 | 0 | NEW | 2.5 | AllplanAttributes - ash_lichte Raumhöhe: 2.5; OKFF: 0; Pset_CoveringCommon - AcousticRating: -
 | WUN-H2-E02-F04 | CEILING | D1 0.001 m | 1215Dfl0000060716/02 | m² | Maler- und Lackierarbeiten | 2 | 0.001 | 0 | 1 | Bekleidung | D1 | 0 | 0 | NEW | AllplanAttributes - OKFF: 0
 | WUN-H2-E02-F04 | CEILING | Aa 0.1 m | 1215Dfl0000160834/01 | m² | Trockenbauarbeiten | 1 | 0.1 | 0 | 1 | Bekleidung | Aa | 0 | 0 | NEW | 2.5 | AllplanAttributes - ash_lichte Raumhöhe: 2.5; OKFF: 0; Pset_CoveringCommon - AcousticRating: -
 | WUN-H2-E02-F04 | CEILING | D1 0.001 m | 1215Dfl0000160834/02 | m² | Maler- und Lackierarbeiten | 2 | 0.001 | 0 | 1 | Bekleidung | D1 | 0 | 0 | NEW | AllplanAttributes - OKFF: 0
 | WUN-H2-E02-F04 | CEILING | A1 0.1 m | 1215Dfl0000148775/01 | m² | Trockenbauarbeiten | 1 | 0.1 | 0 | 1 | Bekleidung | A1 | 0 | 0 | NEW | 2.5 | AllplanAttributes - ash_lichte Raumhöhe: 3.1; OKFF: 0; Pset_CoveringCommon - AcousticRating: -
 | WUN-H2-E02-F04 | CEILING | D1 0.001 m | 1215Dfl0000148775/02 | m² | Maler- und Lackierarbeiten | 2 | 0.001 | 0 | 1 | Bekleidung | D1 | 0 | 0 | NEW | AllplanAttributes - OKFF: 0
 | WUN-H2-E02-F04 | CEILING | A1 0.1 m | 1215Dfl0000008034/01 | m² | Trockenbauarbeiten | 1 | 0.1 | 0 | 1 | Bekleidung | A1 | 0 | 0 | NEW | 2.5 | AllplanAttributes - ash_lichte Raumhöhe: 2.5; OKFF: 0; Pset_CoveringCommon - AcousticRating: -
 | WUN-H2-E02-F04 | CEILING | D1 0.001 m | 1215Dfl0000008034/02 | m² | Maler- und Lackierarbeiten | 2 | 0.001 | 0 | 1 | Bekleidung | D1 | 0 | 0 | NEW | AllplanAttributes - OKFF: 0
 | WUN-H2-E02-F04 | CEILING | A1 0.1 m | 1215Dfl0000162190/01 | m² | Trockenbauarbeiten | 1 | 0.1 | 0 | 1 | Bekleidung | A1 | 0 | 0 | NEW | 2.5 | AllplanAttributes - ash_lichte Raumhöhe: 2.5; OKFF: 0; Pset_CoveringCommon - AcousticRating: -
 | WUN-H2-E02-F04 | CEILING | D1 0.001 m | 1215Dfl0000162190/02 | m² | Maler- und Lackierarbeiten | 2 | 0.001 | 0 | 1 | Bekleidung | D1 | 0 | 0 | NEW | AllplanAttributes - OKFF: 0
PVC Bahnenware Holzoptik | WUN-H2-E02-F11 | FLOORING | Ku1 0.15 m | 1215Bfl0000006833/01 | m² | Bodenbelagsarbeiten | 1 | 0.15 | 0 | 1 | Bodenfläche | Ku1 | 0 | 0 | NEW | AllplanAttributes - Bezeichnung: PVC Bahnenware Holzoptik; Raumnr. Bauherr: 2.11_A2_02; ash B_Aufbau: B9; ash B_Rutschhemmung: R9
Handlauf | WUN-H2-E02-F11 | CLADDING | 97 0.001 m | 1215Sfl0000058349/02 | m² | Maler- und Lackierarbeiten | 2 | 0.001 | 0 | 1 | Seitenfläche | 97 | 0 | 0 | NEW | AllplanAttributes - Bezeichnung: Handlauf
Handlauf | WUN-H2-E02-F11 | CLADDING | 97 0.001 m | 1215Sfl0000057476/02 | m² | Maler- und Lackierarbeiten | 2 | 0.001 | 0 | 1 | Seitenfläche | 97 | 0 | 0 | NEW | AllplanAttributes - Bezeichnung: Handlauf
Handlauf | WUN-H2-E02-F11 | CLADDING | 97 0.001 m | 1215Sfl0000057767/02 | m² | Maler- und Lackierarbeiten | 2 | 0.001 | 0 | 1 | Seitenfläche | 97 | 0 | 0 | NEW | AllplanAttributes - Bezeichnung: Handlauf
Gipsfaserplatten 2-lagig (BSK) | WUN-H2-E02-F11 | CEILING | layer 0.036 m | 1215Dfl0000006834/01 | m² | Trockenbauarbeiten | 1 | 0.036 | 0 | 1 | Deckenfläche |  | 0 | 0 | NEW | 3.15 | AllplanAttributes - Bezeichnung: Gipsfaserplatten 2-lagig (BSK); ash_lichte Raumhöhe: 4.75058
 | WUN-H2-E02-F11 | CEILING | A1 0.1 m | 1215Dfl0000009489/01 | m² | Trockenbauarbeiten | 1 | 0.1 | 0 | 1 | Bekleidung | A1 | 0 | 0 | NEW | 2.5 | AllplanAttributes - ash_lichte Raumhöhe: 2.5; OKFF: 0; Pset_CoveringCommon - AcousticRating: -
 | WUN-H2-E02-F11 | CEILING | D1 0.001 m | 1215Dfl0000009489/02 | m² | Maler- und Lackierarbeiten | 2 | 0.001 | 0 | 1 | Bekleidung | D1 | 0 | 0 | NEW | AllplanAttributes - OKFF: 0
 | WUN-H2-E02-F11 | CEILING | A1 0.1 m | 1215Dfl0000162264/01 | m² | Trockenbauarbeiten | 1 | 0.1 | 0 | 1 | Bekleidung | A1 | 0 | 0 | NEW | 2.5 | AllplanAttributes - ash_lichte Raumhöhe: 2.5; OKFF: 0; Pset_CoveringCommon - AcousticRating: -
 | WUN-H2-E02-F11 | CEILING | D1 0.001 m | 1215Dfl0000162264/02 | m² | Maler- und Lackierarbeiten | 2 | 0.001 | 0 | 1 | Bekleidung | D1 | 0 | 0 | NEW | AllplanAttributes - OKFF: 0
 | WUN-H2-E02-F11 | CEILING | Aa 0.1 m | 1215Dfl0000063199/01 | m² | Trockenbauarbeiten | 1 | 0.1 | 0 | 1 | Bekleidung | Aa | 0 | 0 | NEW | 2.5 | AllplanAttributes - ash_lichte Raumhöhe: 2.5; OKFF: 0; Pset_CoveringCommon - AcousticRating: -
 | WUN-H2-E02-F11 | CEILING | D1 0.001 m | 1215Dfl0000063199/02 | m² | Maler- und Lackierarbeiten | 2 | 0.001 | 0 | 1 | Bekleidung | D1 | 0 | 0 | NEW | AllplanAttributes - OKFF: 0
 | WUN-H2-E02-F11 | CEILING | A1 0.1 m | 1215Dfl0000129533/01 | m² | Trockenbauarbeiten | 1 | 0.1 | 0 | 1 | Bekleidung | A1 | 0 | 0 | NEW | 2.5 | AllplanAttributes - ash_lichte Raumhöhe: 3.1; OKFF: 0; Pset_CoveringCommon - AcousticRating: -
 | WUN-H2-E02-F11 | CEILING | D1 0.001 m | 1215Dfl0000129533/02 | m² | Maler- und Lackierarbeiten | 2 | 0.001 | 0 | 1 | Bekleidung | D1 | 0 | 0 | NEW | AllplanAttributes - OKFF: 0
 | WUN-H2-E02-F11 | CEILING | Aa 0.1 m | 1215Dfl0000160678/01 | m² | Trockenbauarbeiten | 1 | 0.1 | 0 | 1 | Bekleidung | Aa | 0 | 0 | NEW | 2.5 | AllplanAttributes - ash_lichte Raumhöhe: 2.5; OKFF: 0; Pset_CoveringCommon - AcousticRating: -
 | WUN-H2-E02-F11 | CEILING | D1 0.001 m | 1215Dfl0000160678/02 | m² | Maler- und Lackierarbeiten | 2 | 0.001 | 0 | 1 | Bekleidung | D1 | 0 | 0 | NEW | AllplanAttributes - OKFF: 0
PVC Bahnenware Holzoptik | WUN-H2-E02-F10 | FLOORING | Ku1 0.15 m | 1215Bfl0000006839/01 | m² | Bodenbelagsarbeiten | 1 | 0.15 | 0 | 1 | Bodenfläche | Ku1 | 0 | 0 | NEW | AllplanAttributes - Bezeichnung: PVC Bahnenware Holzoptik; Raumnr. Bauherr: 2.11_A2_02; ash B_Aufbau: B9; ash B_Rutschhemmung: R9
Handlauf | WUN-H2-E02-F10 | CLADDING | 97 0.001 m | 1215Sfl0000057185/02 | m² | Maler- und Lackierarbeiten | 2 | 0.001 | 0 | 1 | Seitenfläche | 97 | 0 | 0 | NEW | AllplanAttributes - Bezeichnung: Handlauf
Gipsfaserplatten 2-lagig (BSK) | WUN-H2-E02-F10 | CEILING | layer 0.036 m | 1215Dfl0000006840/01 | m² | Trockenbauarbeiten | 1 | 0.036 | 0 | 1 | Deckenfläche |  | 0 | 0 | NEW | 2.5 | AllplanAttributes - Bezeichnung: Gipsfaserplatten 2-lagig (BSK); ash_lichte Raumhöhe: 4.03489
 | WUN-H2-E02-F10 | CEILING | Aa 0.1 m | 1215Dfl0000063779/01 | m² | Trockenbauarbeiten | 1 | 0.1 | 0 | 1 | Bekleidung | Aa | 0 | 0 | NEW | 2.5 | AllplanAttributes - ash_lichte Raumhöhe: 2.5; OKFF: 0; Pset_CoveringCommon - AcousticRating: -
 | WUN-H2-E02-F10 | CEILING | D1 0.001 m | 1215Dfl0000063779/02 | m² | Maler- und Lackierarbeiten | 2 | 0.001 | 0 | 1 | Bekleidung | D1 | 0 | 0 | NEW | AllplanAttributes - OKFF: 0
 | WUN-H2-E02-F10 | CEILING | A1 0.1 m | 1215Dfl0000152048/01 | m² | Trockenbauarbeiten | 1 | 0.1 | 0 | 1 | Bekleidung | A1 | 0 | 0 | NEW | 2.5 | AllplanAttributes - ash_lichte Raumhöhe: 2.5; OKFF: 0; Pset_CoveringCommon - AcousticRating: -
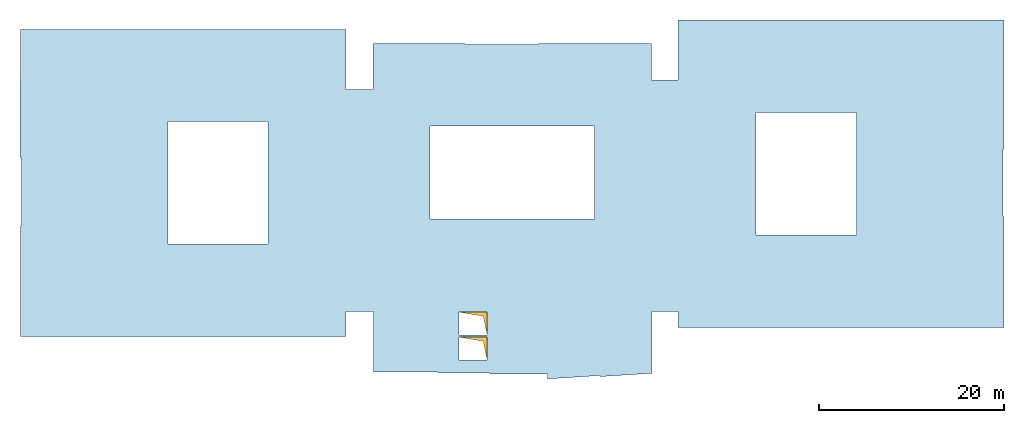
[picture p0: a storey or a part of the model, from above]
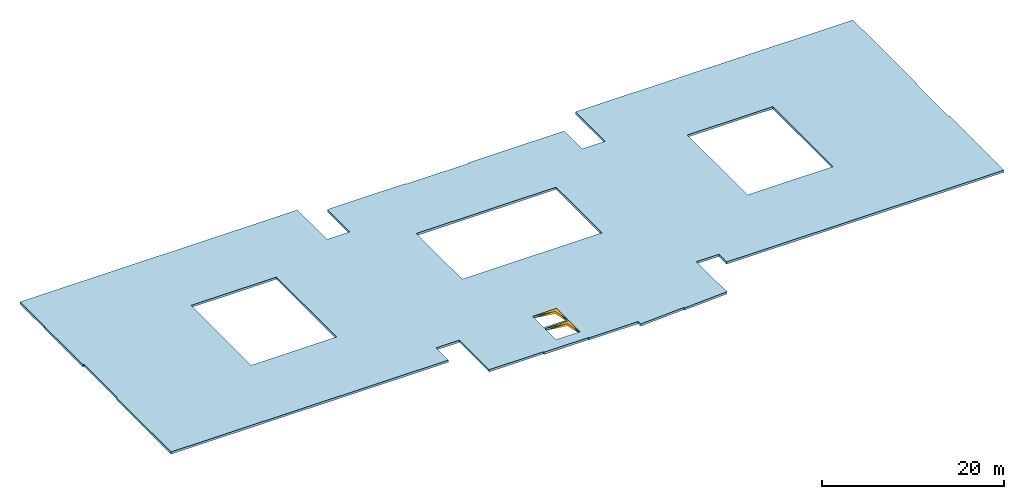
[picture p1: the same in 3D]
Properties of the parts of a building model (IFC4), part 6 of 80

# IfcCovering (3945)
Name | In | PredefinedType | Material | Allright_Bauteil_ID | Abrechnungsart | Gewerk | Schichtnummer | Schichtdicke (m) | Dicke (m) | Faktor | Objektname | AllplanAttributes, Material | Bezugshöhe | Deltahöhe | Status | D_lichte Raumhöhe [Zahl] (m)
 | WUN-H2-E02-F10 | CEILING | D1 0.001 m | 1215Dfl0000152048/02 | m² | Maler- und Lackierarbeiten | 2 | 0.001 | 0 | 1 | Bekleidung | D1 | 0 | 0 | NEW | AllplanAttributes - OKFF: 0
PVC Bahnenware Holzoptik | WUN-H2-E02-F09 | FLOORING | Ku1 0.15 m | 1215Bfl0000006843/01 | m² | Bodenbelagsarbeiten | 1 | 0.15 | 0 | 1 | Bodenfläche | Ku1 | 0 | 0 | NEW | AllplanAttributes - Bezeichnung: PVC Bahnenware Holzoptik; Raumnr. Bauherr: 2.11_A2_02; ash B_Aufbau: B9; ash B_Rutschhemmung: R9
Handlauf | WUN-H2-E02-F09 | CLADDING | 97 0.001 m | 1215Sfl0000056021/02 | m² | Maler- und Lackierarbeiten | 2 | 0.001 | 0 | 1 | Seitenfläche | 97 | 0 | 0 | NEW | AllplanAttributes - Bezeichnung: Handlauf
Handlauf | WUN-H2-E02-F09 | CLADDING | 97 0.001 m | 1215Sfl0000082319/02 | m² | Maler- und Lackierarbeiten | 2 | 0.001 | 0 | 1 | Seitenfläche | 97 | 0 | 0 | NEW | AllplanAttributes - Bezeichnung: Handlauf
Handlauf | WUN-H2-E02-F09 | CLADDING | 97 0.001 m | 1215Sfl0000056312/02 | m² | Maler- und Lackierarbeiten | 2 | 0.001 | 0 | 1 | Seitenfläche | 97 | 0 | 0 | NEW | AllplanAttributes - Bezeichnung: Handlauf
Handlauf | WUN-H2-E02-F09 | CLADDING | 97 0.001 m | 1215Sfl0000056603/02 | m² | Maler- und Lackierarbeiten | 2 | 0.001 | 0 | 1 | Seitenfläche | 97 | 0 | 0 | NEW | AllplanAttributes - Bezeichnung: Handlauf
Gipsfaserplatten 2-lagig (BSK) | WUN-H2-E02-F09 | CEILING | layer 0.036 m | 1215Dfl0000006844/01 | m² | Trockenbauarbeiten | 1 | 0.036 | 0 | 1 | Deckenfläche |  | 0 | 0 | NEW | 3.15 | AllplanAttributes - Bezeichnung: Gipsfaserplatten 2-lagig (BSK); ash_lichte Raumhöhe: 4.72781
 | WUN-H2-E02-F09 | CEILING | A1 0.1 m | 1215Dfl0000162338/01 | m² | Trockenbauarbeiten | 1 | 0.1 | 0 | 1 | Bekleidung | A1 | 0 | 0 | NEW | 2.5 | AllplanAttributes - ash_lichte Raumhöhe: 2.5; OKFF: 0; Pset_CoveringCommon - AcousticRating: -
 | WUN-H2-E02-F09 | CEILING | D1 0.001 m | 1215Dfl0000162338/02 | m² | Maler- und Lackierarbeiten | 2 | 0.001 | 0 | 1 | Bekleidung | D1 | 0 | 0 | NEW | AllplanAttributes - OKFF: 0
 | WUN-H2-E02-F09 | CEILING | Aa 0.1 m | 1215Dfl0000159226/01 | m² | Trockenbauarbeiten | 1 | 0.1 | 0 | 1 | Bekleidung | Aa | 0 | 0 | NEW | 2.5 | AllplanAttributes - ash_lichte Raumhöhe: 2.5; OKFF: 0; Pset_CoveringCommon - AcousticRating: -
 | WUN-H2-E02-F09 | CEILING | D1 0.001 m | 1215Dfl0000159226/02 | m² | Maler- und Lackierarbeiten | 2 | 0.001 | 0 | 1 | Bekleidung | D1 | 0 | 0 | NEW | AllplanAttributes - OKFF: 0
 | WUN-H2-E02-F09 | CEILING | Aa 0.1 m | 1215Dfl0000064367/01 | m² | Trockenbauarbeiten | 1 | 0.1 | 0 | 1 | Bekleidung | Aa | 0 | 0 | NEW | 2.5 | AllplanAttributes - ash_lichte Raumhöhe: 2.5; OKFF: 0; Pset_CoveringCommon - AcousticRating: -
 | WUN-H2-E02-F09 | CEILING | D1 0.001 m | 1215Dfl0000064367/02 | m² | Maler- und Lackierarbeiten | 2 | 0.001 | 0 | 1 | Bekleidung | D1 | 0 | 0 | NEW | AllplanAttributes - OKFF: 0
 | WUN-H2-E02-F09 | CEILING | A1 0.1 m | 1215Dfl0000009198/01 | m² | Trockenbauarbeiten | 1 | 0.1 | 0 | 1 | Bekleidung | A1 | 0 | 0 | NEW | 2.5 | AllplanAttributes - ash_lichte Raumhöhe: 2.5; OKFF: 0; Pset_CoveringCommon - AcousticRating: -
 | WUN-H2-E02-F09 | CEILING | D1 0.001 m | 1215Dfl0000009198/02 | m² | Maler- und Lackierarbeiten | 2 | 0.001 | 0 | 1 | Bekleidung | D1 | 0 | 0 | NEW | AllplanAttributes - OKFF: 0
 | WUN-H2-E02-F09 | CEILING | A1 0.1 m | 1215Dfl0000125747/01 | m² | Trockenbauarbeiten | 1 | 0.1 | 0 | 1 | Bekleidung | A1 | 0 | 0 | NEW | 2.5 | AllplanAttributes - ash_lichte Raumhöhe: 3.1; OKFF: 0; Pset_CoveringCommon - AcousticRating: -
 | WUN-H2-E02-F09 | CEILING | D1 0.001 m | 1215Dfl0000125747/02 | m² | Maler- und Lackierarbeiten | 2 | 0.001 | 0 | 1 | Bekleidung | D1 | 0 | 0 | NEW | AllplanAttributes - OKFF: 0
Fliesen Großformat | WUN-H2-E02-F01 | FLOORING | Ku1 0.15 m | 1215Bfl0000006874/01 | m² | Bodenbelagsarbeiten | 1 | 0.15 | 0 | 1 | Bodenfläche | Ku1 | 0 | 0 | NEW | AllplanAttributes - Bezeichnung: Fliesen Großformat; Raumnr. Bauherr: B8; ash B_Aufbau: B9; ash B_Rutschhemmung: R9
Gipsfaserplatten 2-lagig (BSK) | WUN-H2-E02-F01 | CEILING | layer 0.036 m | 1215Dfl0000006873/01 | m² | Trockenbauarbeiten | 1 | 0.036 | 0 | 1 | Deckenfläche |  | 0 | 0 | NEW | 2.75 | AllplanAttributes - Bezeichnung: Gipsfaserplatten 2-lagig (BSK); ash_lichte Raumhöhe: 2.75
 | WUN-H2-E02-F01 | CEILING | Installationshöhe 0.514 m | 1215Dfl0000006873/02 | m² | Trockenbauarbeiten | 2 | 0.514 | 0 | 1 | Bekleidung | Installationshöhe | 0 | 0 | NEW
 | WUN-H2-E02-F01 | CEILING | A1 0.1 m | 1215Dfl0000006873/03 | m² | Trockenbauarbeiten | 3 | 0.1 | 0 | 1 | Bekleidung | A1 | 0 | 0 | NEW | Pset_CoveringCommon - FireRating: F30; AcousticRating: -
 | WUN-H2-E02-F01 | CEILING | D1 0.001 m | 1215Dfl0000006873/04 | m² | Maler- und Lackierarbeiten | 4 | 0.001 | 0 | 1 | Bekleidung | D1 | 0 | 0 | NEW
PVC Bahnenware Holzoptik | WUN-H2-E02-F08 | FLOORING | Ku1 0.15 m | 1215Bfl0000006849/01 | m² | Bodenbelagsarbeiten | 1 | 0.15 | 0 | 1 | Bodenfläche | Ku1 | 0 | 0 | NEW | AllplanAttributes - Bezeichnung: PVC Bahnenware Holzoptik; Raumnr. Bauherr: 2.11_A2_02; ash B_Aufbau: B9; ash B_Rutschhemmung: R9
Acrovyn | WUN-H2-E02-F08 | CLADDING | 84 0.001 m | 1215Sfl0000048745/02 | m² | Maler- und Lackierarbeiten | 2 | 0.001 | 0 | 1 | Seitenfläche | 84 | 0 | 0 | NEW | AllplanAttributes - Bezeichnung: Acrovyn
Gipsfaserplatten 2-lagig (BSK) | WUN-H2-E02-F08 | CEILING | layer 0.036 m | 1215Dfl0000008325/01 | m² | Trockenbauarbeiten | 1 | 0.036 | 0 | 1 | Deckenfläche |  | 0 | 0 | NEW | 2.5 | AllplanAttributes - Bezeichnung: Gipsfaserplatten 2-lagig (BSK); ash_lichte Raumhöhe: 2.5
 | WUN-H2-E02-F08 | CEILING | Installationshöhe 0.664 m | 1215Dfl0000008325/02 | m² | Trockenbauarbeiten | 2 | 0.664 | 0 | 1 | Bekleidung | Installationshöhe | 0 | 0 | NEW
 | WUN-H2-E02-F08 | CEILING | A1 0.2 m | 1215Dfl0000008325/03 | m² | Trockenbauarbeiten | 3 | 0.2 | 0 | 1 | Bekleidung | A1 | 0 | 0 | NEW | Pset_CoveringCommon - FireRating: F30; AcousticRating: -
 | WUN-H2-E02-F08 | CEILING | D1 0.001 m | 1215Dfl0000008325/04 | m² | Maler- und Lackierarbeiten | 4 | 0.001 | 0 | 1 | Bekleidung | D1 | 0 | 0 | NEW
Gipsfaserplatten 2-lagig (BSK) | WUN-H2-E02-F08 | CEILING | layer 0.036 m | 1215Dfl0000061946/01 | m² | Trockenbauarbeiten | 1 | 0.036 | 0 | 1 | Deckenfläche |  | 0 | 0 | NEW | 2.5 | AllplanAttributes - Bezeichnung: Gipsfaserplatten 2-lagig (BSK); ash_lichte Raumhöhe: 2.5
 | WUN-H2-E02-F08 | CEILING | Installationshöhe 0.664 m | 1215Dfl0000061946/02 | m² | Trockenbauarbeiten | 2 | 0.664 | 0 | 1 | Bekleidung | Installationshöhe | 0 | 0 | NEW
 | WUN-H2-E02-F08 | CEILING | Aa 0.2 m | 1215Dfl0000061946/03 | m² | Trockenbauarbeiten | 3 | 0.2 | 0 | 1 | Bekleidung | Aa | 0 | 0 | NEW | Pset_CoveringCommon - FireRating: F30; AcousticRating: -
 | WUN-H2-E02-F08 | CEILING | D1 0.001 m | 1215Dfl0000061946/04 | m² | Maler- und Lackierarbeiten | 4 | 0.001 | 0 | 1 | Bekleidung | D1 | 0 | 0 | NEW
Sichtbetonklasse SB3 | WUN-H2-E02-T03 | CLADDING | 03 0.001 m | 1215Sfl0000088486/02 | m² | Putz- und Stuckarbeiten | 2 | 0.001 | 0 | 1 | Seitenfläche | 03 | 0 | 0 | NEW | AllplanAttributes - Bezeichnung: Sichtbetonklasse SB3
Sichtbetonklasse SB3 | WUN-H2-E02-T03 | CLADDING | 47 0.001 m | 1215Sfl0000088486/04 | m² | Maler- und Lackierarbeiten | 4 | 0.001 | 0 | 1 | Seitenfläche | 47 | 0 | 0 | NEW
Fliesen Großformat | WUN-H2-E02-T03 | FLOORING | Fl12 0.1 m | 1215Bfl0000078306/01 | m² | Bodenbelagsarbeiten | 1 | 0.1 | 0 | 1 | Bodenfläche | Fl12 | 0 | 0 | NEW | AllplanAttributes - Bezeichnung: Fliesen Großformat; ash B_Aufbau: B7; ash B_Rutschhemmung: R10
Fliesen Großformat | WUN-H2-E02-T03 | FLOORING | Fl12 0.06 m | 1215Bfl0000078110/01 | m² | Bodenbelagsarbeiten | 1 | 0.06 | 0 | 1 | Bodenfläche | Fl12 | 0 | 0 | NEW | AllplanAttributes - Bezeichnung: Fliesen Großformat; ash B_Aufbau: B6; ash B_Rutschhemmung: R10
Gipsfaserplatten 2-lagig (BSK) | WUN-H2-E02-T03 | CEILING | layer 0.036 m | 1215Dfl0000032617/01 | m² | Trockenbauarbeiten | 1 | 0.036 | 0 | 1 | Deckenfläche |  | 0 | 0 | NEW | 3.1 | AllplanAttributes - Bezeichnung: Gipsfaserplatten 2-lagig (BSK); ash_lichte Raumhöhe: 3.1
 | WUN-H2-E02-T03 | CEILING | Installationshöhe 0.164 m | 1215Dfl0000032617/02 | m² | Trockenbauarbeiten | 2 | 0.164 | 0 | 1 | Bekleidung | Installationshöhe | 0 | 0 | NEW
 | WUN-H2-E02-T03 | CEILING | A1 0.1 m | 1215Dfl0000032617/03 | m² | Trockenbauarbeiten | 3 | 0.1 | 0 | 1 | Bekleidung | A1 | 0 | 0 | NEW | Pset_CoveringCommon - FireRating: F60; AcousticRating: -
 | WUN-H2-E02-T03 | CEILING | D1 0.001 m | 1215Dfl0000032617/04 | m² | Maler- und Lackierarbeiten | 4 | 0.001 | 0 | 1 | Bekleidung | D1 | 0 | 0 | NEW
Sichtbetonklasse SB3 | WUN-H2-E02-T04 | CLADDING | 03 0.001 m | 1215Sfl0000088485/02 | m² | Putz- und Stuckarbeiten | 2 | 0.001 | 0 | 1 | Seitenfläche | 03 | 0 | 0 | NEW | AllplanAttributes - Bezeichnung: Sichtbetonklasse SB3
Sichtbetonklasse SB3 | WUN-H2-E02-T04 | CLADDING | 47 0.001 m | 1215Sfl0000088485/04 | m² | Maler- und Lackierarbeiten | 4 | 0.001 | 0 | 1 | Seitenfläche | 47 | 0 | 0 | NEW
Fliesen Großformat | WUN-H2-E02-T04 | FLOORING | Fl12 0.06 m | 1215Bfl0000089511/01 | m² | Bodenbelagsarbeiten | 1 | 0.06 | 0 | 1 | Bodenfläche | Fl12 | 0 | 0 | NEW | AllplanAttributes - Bezeichnung: Fliesen Großformat; ash B_Aufbau: B6; ash B_Rutschhemmung: R10
Fliesen Großformat | WUN-H2-E02-T04 | FLOORING | Fl12 0.1 m | 1215Bfl0000079559/01 | m² | Bodenbelagsarbeiten | 1 | 0.1 | 0 | 1 | Bodenfläche | Fl12 | 0 | 0 | NEW | AllplanAttributes - Bezeichnung: Fliesen Großformat; ash B_Aufbau: B7; ash B_Rutschhemmung: R10
Gipsfaserplatten 2-lagig (BSK) | WUN-H2-E02-T04 | CEILING | layer 0.036 m | 1215Dfl0000162812/01 | m² | Trockenbauarbeiten | 1 | 0.036 | 0 | 1 | Deckenfläche |  | 0 | 0 | NEW | 2.75 | AllplanAttributes - Bezeichnung: Gipsfaserplatten 2-lagig (BSK); ash_lichte Raumhöhe: 3.49741
 | WUN-H2-E02-T04 | CEILING | A1 0.1 m | 1215Dfl0000091239/01 | m² | Trockenbauarbeiten | 1 | 0.1 | 0 | 1 | Bekleidung | A1 | 0 | 0 | NEW | 4.075 | Pset_CoveringCommon - FireRating: F60; AcousticRating: -; AllplanAttributes - ash_lichte Raumhöhe: 2.5
 | WUN-H2-E02-T04 | CEILING | D1 0.001 m | 1215Dfl0000091239/02 | m² | Maler- und Lackierarbeiten | 2 | 0.001 | 0 | 1 | Bekleidung | D1 | 0 | 0 | NEW
Sichtbetonklasse SB3 | WUN-H2-E02-T02 | CLADDING | 03 0.001 m | 1215Sfl0000088487/02 | m² | Putz- und Stuckarbeiten | 2 | 0.001 | 0 | 1 | Seitenfläche | 03 | 0 | 0 | NEW | AllplanAttributes - Bezeichnung: Sichtbetonklasse SB3
Sichtbetonklasse SB3 | WUN-H2-E02-T02 | CLADDING | 47 0.001 m | 1215Sfl0000088487/04 | m² | Maler- und Lackierarbeiten | 4 | 0.001 | 0 | 1 | Seitenfläche | 47 | 0 | 0 | NEW
Fliesen Großformat | WUN-H2-E02-T02 | FLOORING | Fl12 0.1 m | 1215Bfl0000068279/01 | m² | Bodenbelagsarbeiten | 1 | 0.1 | 0 | 1 | Bodenfläche | Fl12 | 0 | 0 | NEW | AllplanAttributes - Bezeichnung: Fliesen Großformat; ash B_Aufbau: B7; ash B_Rutschhemmung: R10
Fliesen Großformat | WUN-H2-E02-T02 | FLOORING | Fl12 0.06 m | 1215Bfl0000068631/01 | m² | Bodenbelagsarbeiten | 1 | 0.06 | 0 | 1 | Bodenfläche | Fl12 | 0 | 0 | NEW | AllplanAttributes - Bezeichnung: Fliesen Großformat; ash B_Aufbau: B6; ash B_Rutschhemmung: R10
Gipsfaserplatten 2-lagig (BSK) | WUN-H2-E02-T02 | CEILING | layer 0.036 m | 1215Dfl0000162820/01 | m² | Trockenbauarbeiten | 1 | 0.036 | 0 | 1 | Deckenfläche |  | 0 | 0 | NEW | 2.75 | AllplanAttributes - Bezeichnung: Gipsfaserplatten 2-lagig (BSK); ash_lichte Raumhöhe: 3.49557
 | WUN-H2-E02-T02 | CEILING | A1 0.1 m | 1215Dfl0000091828/01 | m² | Trockenbauarbeiten | 1 | 0.1 | 0 | 1 | Bekleidung | A1 | 0 | 0 | NEW | Pset_CoveringCommon - FireRating: F60; AcousticRating: -; AllplanAttributes - ash_lichte Raumhöhe: 2.5
 | WUN-H2-E02-T02 | CEILING | D1 0.001 m | 1215Dfl0000091828/02 | m² | Maler- und Lackierarbeiten | 2 | 0.001 | 0 | 1 | Bekleidung | D1 | 0 | 0 | NEW
a-sh Abschluss Abhangdecke | H2 Ebene +2 | CEILING |  | 1216HWa0813296072 | m² |  |  |  |  |  | Gesamtwand |  |  |  | NEW | AllplanAttributes - Bezeichnung: a-sh Abschluss Abhangdecke; Attributset-Objekt: Covering; Object Layer Attributes #1, 2D Interaktion: yes; Object Layer Attributes #1, Gewerk: Trockenbauarbeiten; Object Layer Attributes #1, Material: A; Object Layer Attributes #1, Attributset-Objekt: Covering; Object Layer Attributes #1, Allright_Bauteil_ID: 1216Wa 0813296073; Object Layer Attributes #1, Abrechnungsart: m²; Object Layer Attributes #1, Objektname: Wand; Object Layer Attributes #1, Bezeichnung: a-sh Abschluss Abhangdecke; Pset_CoveringCommon - IsExternal: no; FireRating: -; ThermalTransmittance: 0 W/K/m2; Reference: Reference
a-sh Abschluss Abhangdecke | H2 Ebene +2 | CEILING |  | 1216HWa0813296097 | m² |  |  |  |  |  | Gesamtwand |  |  |  | NEW | AllplanAttributes - Bezeichnung: a-sh Abschluss Abhangdecke; Attributset-Objekt: Covering; Object Layer Attributes #1, 2D Interaktion: yes; Object Layer Attributes #1, Gewerk: Trockenbauarbeiten; Object Layer Attributes #1, Material: A; Object Layer Attributes #1, Attributset-Objekt: Covering; Object Layer Attributes #1, Allright_Bauteil_ID: 1216Wa 0813296098; Object Layer Attributes #1, Abrechnungsart: m²; Object Layer Attributes #1, Objektname: Wand; Object Layer Attributes #1, Bezeichnung: a-sh Abschluss Abhangdecke; Pset_CoveringCommon - IsExternal: no; FireRating: -; ThermalTransmittance: 0 W/K/m2; Reference: Reference
a-sh Abschluss Abhangdecke | H2 Ebene +2 | CEILING |  | 1216HWa0813296120 | m² |  |  |  |  |  | Gesamtwand |  |  |  | NEW | AllplanAttributes - Bezeichnung: a-sh Abschluss Abhangdecke; Attributset-Objekt: Covering; Object Layer Attributes #1, 2D Interaktion: yes; Object Layer Attributes #1, Gewerk: Trockenbauarbeiten; Object Layer Attributes #1, Material: A; Object Layer Attributes #1, Attributset-Objekt: Covering; Object Layer Attributes #1, Allright_Bauteil_ID: 1216Wa 0813296121; Object Layer Attributes #1, Abrechnungsart: m²; Object Layer Attributes #1, Objektname: Wand; Object Layer Attributes #1, Bezeichnung: a-sh Abschluss Abhangdecke; Pset_CoveringCommon - IsExternal: no; FireRating: -; ThermalTransmittance: 0 W/K/m2; Reference: Reference
a-sh Abschluss Abhangdecke | H2 Ebene +2 | CEILING |  | 1216HWa0813296108 | m² |  |  |  |  |  | Gesamtwand |  |  |  | NEW | AllplanAttributes - Bezeichnung: a-sh Abschluss Abhangdecke; Attributset-Objekt: Covering; Object Layer Attributes #1, 2D Interaktion: yes; Object Layer Attributes #1, Gewerk: Trockenbauarbeiten; Object Layer Attributes #1, Material: A; Object Layer Attributes #1, Attributset-Objekt: Covering; Object Layer Attributes #1, Allright_Bauteil_ID: 1216Wa 0813296109; Object Layer Attributes #1, Abrechnungsart: m²; Object Layer Attributes #1, Objektname: Wand; Object Layer Attributes #1, Bezeichnung: a-sh Abschluss Abhangdecke; Pset_CoveringCommon - IsExternal: no; FireRating: -; ThermalTransmittance: 0 W/K/m2; Reference: Reference
a-sh Abschluss Abhangdecke | H2 Ebene +2 | CEILING |  | 1216HWa0813296092 | m² |  |  |  |  |  | Gesamtwand |  |  |  | NEW | AllplanAttributes - Bezeichnung: a-sh Abschluss Abhangdecke; Attributset-Objekt: Covering; Object Layer Attributes #1, 2D Interaktion: yes; Object Layer Attributes #1, Gewerk: Trockenbauarbeiten; Object Layer Attributes #1, Material: A; Object Layer Attributes #1, Attributset-Objekt: Covering; Object Layer Attributes #1, Allright_Bauteil_ID: 1216Wa 0813296093; Object Layer Attributes #1, Abrechnungsart: m²; Object Layer Attributes #1, Objektname: Wand; Object Layer Attributes #1, Bezeichnung: a-sh Abschluss Abhangdecke; Pset_CoveringCommon - IsExternal: no; FireRating: -; ThermalTransmittance: 0 W/K/m2; Reference: Reference
a-sh Abschluss Abhangdecke | H2 Ebene +2 | CEILING |  | 1216HWa0813296163 | m² |  |  |  |  |  | Gesamtwand |  |  |  | NEW | AllplanAttributes - Bezeichnung: a-sh Abschluss Abhangdecke; Attributset-Objekt: Covering; Object Layer Attributes #1, 2D Interaktion: yes; Object Layer Attributes #1, Gewerk: Trockenbauarbeiten; Object Layer Attributes #1, Material: A; Object Layer Attributes #1, Attributset-Objekt: Covering; Object Layer Attributes #1, Allright_Bauteil_ID: 1216Wa 0813296164; Object Layer Attributes #1, Abrechnungsart: m²; Object Layer Attributes #1, Objektname: Wand; Object Layer Attributes #1, Bezeichnung: a-sh Abschluss Abhangdecke; Pset_CoveringCommon - IsExternal: no; FireRating: -; ThermalTransmittance: 0 W/K/m2; Reference: Reference
a-sh Abschluss Abhangdecke | H2 Ebene +2 | CEILING |  | 1216HWa0813296168 | m² |  |  |  |  |  | Gesamtwand |  |  |  | NEW | AllplanAttributes - Bezeichnung: a-sh Abschluss Abhangdecke; Attributset-Objekt: Covering; Object Layer Attributes #1, 2D Interaktion: yes; Object Layer Attributes #1, Gewerk: Trockenbauarbeiten; Object Layer Attributes #1, Material: A; Object Layer Attributes #1, Attributset-Objekt: Covering; Object Layer Attributes #1, Allright_Bauteil_ID: 1216Wa 0813296169; Object Layer Attributes #1, Abrechnungsart: m²; Object Layer Attributes #1, Objektname: Wand; Object Layer Attributes #1, Bezeichnung: a-sh Abschluss Abhangdecke; Pset_CoveringCommon - IsExternal: no; FireRating: -; ThermalTransmittance: 0 W/K/m2; Reference: Reference
a-sh Abschluss Abhangdecke | H2 Ebene +2 | CEILING |  | 1216HWa0813296203 | m² |  |  |  |  |  | Gesamtwand |  |  |  | NEW | AllplanAttributes - Bezeichnung: a-sh Abschluss Abhangdecke; Attributset-Objekt: Covering; Object Layer Attributes #1, 2D Interaktion: yes; Object Layer Attributes #1, Gewerk: Trockenbauarbeiten; Object Layer Attributes #1, Material: A; Object Layer Attributes #1, Attributset-Objekt: Covering; Object Layer Attributes #1, Allright_Bauteil_ID: 1216Wa 0813296204; Object Layer Attributes #1, Abrechnungsart: m²; Object Layer Attributes #1, Objektname: Wand; Object Layer Attributes #1, Bezeichnung: a-sh Abschluss Abhangdecke; Pset_CoveringCommon - IsExternal: no; FireRating: -; ThermalTransmittance: 0 W/K/m2; Reference: Reference
a-sh Abschluss Abhangdecke | H2 Ebene +2 | CEILING |  | 1216HWa0813296218 | m² |  |  |  |  |  | Gesamtwand |  |  |  | NEW | AllplanAttributes - Bezeichnung: a-sh Abschluss Abhangdecke; Attributset-Objekt: Covering; Object Layer Attributes #1, 2D Interaktion: yes; Object Layer Attributes #1, Gewerk: Trockenbauarbeiten; Object Layer Attributes #1, Material: A; Object Layer Attributes #1, Attributset-Objekt: Covering; Object Layer Attributes #1, Allright_Bauteil_ID: 1216Wa 0813296219; Object Layer Attributes #1, Abrechnungsart: m²; Object Layer Attributes #1, Objektname: Wand; Object Layer Attributes #1, Bezeichnung: a-sh Abschluss Abhangdecke; Pset_CoveringCommon - IsExternal: no; FireRating: -; ThermalTransmittance: 0 W/K/m2; Reference: Reference
a-sh Abschluss Abhangdecke | H2 Ebene +2 | CEILING |  | 1216HWa0813296208 | m² |  |  |  |  |  | Gesamtwand |  |  |  | NEW | AllplanAttributes - Bezeichnung: a-sh Abschluss Abhangdecke; Attributset-Objekt: Covering; Object Layer Attributes #1, 2D Interaktion: yes; Object Layer Attributes #1, Gewerk: Trockenbauarbeiten; Object Layer Attributes #1, Material: A; Object Layer Attributes #1, Attributset-Objekt: Covering; Object Layer Attributes #1, Allright_Bauteil_ID: 1216Wa 0813296209; Object Layer Attributes #1, Abrechnungsart: m²; Object Layer Attributes #1, Objektname: Wand; Object Layer Attributes #1, Bezeichnung: a-sh Abschluss Abhangdecke; Pset_CoveringCommon - IsExternal: no; FireRating: -; ThermalTransmittance: 0 W/K/m2; Reference: Reference
a-sh Abschluss Abhangdecke | H2 Ebene +2 | CEILING |  | 1216HWa0813296238 | m² |  |  |  |  |  | Gesamtwand |  |  |  | NEW | AllplanAttributes - Bezeichnung: a-sh Abschluss Abhangdecke; Attributset-Objekt: Covering; Object Layer Attributes #1, 2D Interaktion: yes; Object Layer Attributes #1, Gewerk: Trockenbauarbeiten; Object Layer Attributes #1, Material: A; Object Layer Attributes #1, Attributset-Objekt: Covering; Object Layer Attributes #1, Allright_Bauteil_ID: 1216Wa 0813296239; Object Layer Attributes #1, Abrechnungsart: m²; Object Layer Attributes #1, Objektname: Wand; Object Layer Attributes #1, Bezeichnung: a-sh Abschluss Abhangdecke; Pset_CoveringCommon - IsExternal: no; FireRating: -; ThermalTransmittance: 0 W/K/m2; Reference: Reference
a-sh Abschluss Abhangdecke | H2 Ebene +2 | CEILING |  | 1216HWa0813296253 | m² |  |  |  |  |  | Gesamtwand |  |  |  | NEW | AllplanAttributes - Bezeichnung: a-sh Abschluss Abhangdecke; Attributset-Objekt: Covering; Object Layer Attributes #1, 2D Interaktion: yes; Object Layer Attributes #1, Gewerk: Trockenbauarbeiten; Object Layer Attributes #1, Material: A; Object Layer Attributes #1, Attributset-Objekt: Covering; Object Layer Attributes #1, Allright_Bauteil_ID: 1216Wa 0813296254; Object Layer Attributes #1, Abrechnungsart: m²; Object Layer Attributes #1, Objektname: Wand; Object Layer Attributes #1, Bezeichnung: a-sh Abschluss Abhangdecke; Pset_CoveringCommon - IsExternal: no; FireRating: -; ThermalTransmittance: 0 W/K/m2; Reference: Reference
a-sh Abschluss Abhangdecke | H2 Ebene +2 | CEILING |  | 1216HWa0813296243 | m² |  |  |  |  |  | Gesamtwand |  |  |  | NEW | AllplanAttributes - Bezeichnung: a-sh Abschluss Abhangdecke; Attributset-Objekt: Covering; Object Layer Attributes #1, 2D Interaktion: yes; Object Layer Attributes #1, Gewerk: Trockenbauarbeiten; Object Layer Attributes #1, Material: A; Object Layer Attributes #1, Attributset-Objekt: Covering; Object Layer Attributes #1, Allright_Bauteil_ID: 1216Wa 0813296244; Object Layer Attributes #1, Abrechnungsart: m²; Object Layer Attributes #1, Objektname: Wand; Object Layer Attributes #1, Bezeichnung: a-sh Abschluss Abhangdecke; Pset_CoveringCommon - IsExternal: no; FireRating: -; ThermalTransmittance: 0 W/K/m2; Reference: Reference
a-sh Abschluss Abhangdecke | H2 Ebene +2 | CEILING |  | 1216HWa0813296265 | m² |  |  |  |  |  | Gesamtwand |  |  |  | NEW | AllplanAttributes - Bezeichnung: a-sh Abschluss Abhangdecke; Attributset-Objekt: Covering; Object Layer Attributes #1, 2D Interaktion: yes; Object Layer Attributes #1, Gewerk: Trockenbauarbeiten; Object Layer Attributes #1, Material: A; Object Layer Attributes #1, Attributset-Objekt: Covering; Object Layer Attributes #1, Allright_Bauteil_ID: 1216Wa 0813296266; Object Layer Attributes #1, Abrechnungsart: m²; Object Layer Attributes #1, Objektname: Wand; Object Layer Attributes #1, Bezeichnung: a-sh Abschluss Abhangdecke; Pset_CoveringCommon - IsExternal: no; FireRating: -; ThermalTransmittance: 0 W/K/m2; Reference: Reference
a-sh Abschluss Abhangdecke | H2 Ebene +2 | CEILING |  | 1216HWa0813296274 | m² |  |  |  |  |  | Gesamtwand |  |  |  | NEW | AllplanAttributes - Bezeichnung: a-sh Abschluss Abhangdecke; Attributset-Objekt: Covering; Object Layer Attributes #1, 2D Interaktion: yes; Object Layer Attributes #1, Gewerk: Trockenbauarbeiten; Object Layer Attributes #1, Material: A; Object Layer Attributes #1, Attributset-Objekt: Covering; Object Layer Attributes #1, Allright_Bauteil_ID: 1216Wa 0813296275; Object Layer Attributes #1, Abrechnungsart: m²; Object Layer Attributes #1, Objektname: Wand; Object Layer Attributes #1, Bezeichnung: a-sh Abschluss Abhangdecke; Pset_CoveringCommon - IsExternal: no; FireRating: -; ThermalTransmittance: 0 W/K/m2; Reference: Reference
a-sh Abschluss Abhangdecke | H2 Ebene +2 | CEILING |  | 1216HWa0813303719 | m² |  |  |  |  |  | Gesamtwand |  |  |  | NEW | AllplanAttributes - Bezeichnung: a-sh Abschluss Abhangdecke; Attributset-Objekt: Covering; Object Layer Attributes #1, 2D Interaktion: yes; Object Layer Attributes #1, Gewerk: Trockenbauarbeiten; Object Layer Attributes #1, Material: A; Object Layer Attributes #1, Attributset-Objekt: Covering; Object Layer Attributes #1, Allright_Bauteil_ID: 1216Wa 0813302907; Object Layer Attributes #1, Abrechnungsart: m²; Object Layer Attributes #1, Objektname: Wand; Object Layer Attributes #1, Bezeichnung: a-sh Abschluss Abhangdecke; Pset_CoveringCommon - IsExternal: no; FireRating: -; ThermalTransmittance: 0 W/K/m2; Reference: Reference
a-sh Abschluss Abhangdecke | H2 Ebene +2 | CEILING |  | 1216HWa0813303721 | m² |  |  |  |  |  | Gesamtwand |  |  |  | NEW | AllplanAttributes - Bezeichnung: a-sh Abschluss Abhangdecke; Attributset-Objekt: Covering; Object Layer Attributes #1, 2D Interaktion: yes; Object Layer Attributes #1, Gewerk: Trockenbauarbeiten; Object Layer Attributes #1, Material: A; Object Layer Attributes #1, Attributset-Objekt: Covering; Object Layer Attributes #1, Allright_Bauteil_ID: 1216Wa 0813302909; Object Layer Attributes #1, Abrechnungsart: m²; Object Layer Attributes #1, Objektname: Wand; Object Layer Attributes #1, Bezeichnung: a-sh Abschluss Abhangdecke; Pset_CoveringCommon - IsExternal: no; FireRating: -; ThermalTransmittance: 0 W/K/m2; Reference: Reference
a-sh Abschluss Abhangdecke | H2 Ebene +2 | CEILING |  | 1216HWa0813303723 | m² |  |  |  |  |  | Gesamtwand |  |  |  | NEW | AllplanAttributes - Bezeichnung: a-sh Abschluss Abhangdecke; Attributset-Objekt: Covering; Object Layer Attributes #1, 2D Interaktion: yes; Object Layer Attributes #1, Gewerk: Trockenbauarbeiten; Object Layer Attributes #1, Material: A; Object Layer Attributes #1, Attributset-Objekt: Covering; Object Layer Attributes #1, Allright_Bauteil_ID: 1216Wa 0813302911; Object Layer Attributes #1, Abrechnungsart: m²; Object Layer Attributes #1, Objektname: Wand; Object Layer Attributes #1, Bezeichnung: a-sh Abschluss Abhangdecke; Pset_CoveringCommon - IsExternal: no; FireRating: -; ThermalTransmittance: 0 W/K/m2; Reference: Reference
a-sh Abschluss Abhangdecke | H2 Ebene +2 | CEILING |  | 1216HWa0813303725 | m² |  |  |  |  |  | Gesamtwand |  |  |  | NEW | AllplanAttributes - Bezeichnung: a-sh Abschluss Abhangdecke; Attributset-Objekt: Covering; Object Layer Attributes #1, 2D Interaktion: yes; Object Layer Attributes #1, Gewerk: Trockenbauarbeiten; Object Layer Attributes #1, Material: A; Object Layer Attributes #1, Attributset-Objekt: Covering; Object Layer Attributes #1, Allright_Bauteil_ID: 1216Wa 0813302913; Object Layer Attributes #1, Abrechnungsart: m²; Object Layer Attributes #1, Objektname: Wand; Object Layer Attributes #1, Bezeichnung: a-sh Abschluss Abhangdecke; Pset_CoveringCommon - IsExternal: no; FireRating: -; ThermalTransmittance: 0 W/K/m2; Reference: Reference
a-sh Abschluss Abhangdecke | H2 Ebene +2 | CEILING |  | 1216HWa0813303727 | m² |  |  |  |  |  | Gesamtwand |  |  |  | NEW | AllplanAttributes - Bezeichnung: a-sh Abschluss Abhangdecke; Attributset-Objekt: Covering; Object Layer Attributes #1, 2D Interaktion: yes; Object Layer Attributes #1, Gewerk: Trockenbauarbeiten; Object Layer Attributes #1, Material: A; Object Layer Attributes #1, Attributset-Objekt: Covering; Object Layer Attributes #1, Allright_Bauteil_ID: 1216Wa 0813302915; Object Layer Attributes #1, Abrechnungsart: m²; Object Layer Attributes #1, Objektname: Wand; Object Layer Attributes #1, Bezeichnung: a-sh Abschluss Abhangdecke; Pset_CoveringCommon - IsExternal: no; FireRating: -; ThermalTransmittance: 0 W/K/m2; Reference: Reference
a-sh Abschluss Abhangdecke | H2 Ebene +2 | CEILING |  | 1216HWa0813303729 | m² |  |  |  |  |  | Gesamtwand |  |  |  | NEW | AllplanAttributes - Bezeichnung: a-sh Abschluss Abhangdecke; Attributset-Objekt: Covering; Object Layer Attributes #1, 2D Interaktion: yes; Object Layer Attributes #1, Gewerk: Trockenbauarbeiten; Object Layer Attributes #1, Material: A; Object Layer Attributes #1, Attributset-Objekt: Covering; Object Layer Attributes #1, Allright_Bauteil_ID: 1216Wa 0813302917; Object Layer Attributes #1, Abrechnungsart: m²; Object Layer Attributes #1, Objektname: Wand; Object Layer Attributes #1, Bezeichnung: a-sh Abschluss Abhangdecke; Pset_CoveringCommon - IsExternal: no; FireRating: -; ThermalTransmittance: 0 W/K/m2; Reference: Reference
a-sh Abschluss Abhangdecke | H2 Ebene +2 | CEILING |  | 1216HWa0813303731 | m² |  |  |  |  |  | Gesamtwand |  |  |  | NEW | AllplanAttributes - Bezeichnung: a-sh Abschluss Abhangdecke; Attributset-Objekt: Covering; Object Layer Attributes #1, 2D Interaktion: yes; Object Layer Attributes #1, Gewerk: Trockenbauarbeiten; Object Layer Attributes #1, Material: A; Object Layer Attributes #1, Attributset-Objekt: Covering; Object Layer Attributes #1, Allright_Bauteil_ID: 1216Wa 0813302919; Object Layer Attributes #1, Abrechnungsart: m²; Object Layer Attributes #1, Objektname: Wand; Object Layer Attributes #1, Bezeichnung: a-sh Abschluss Abhangdecke; Pset_CoveringCommon - IsExternal: no; FireRating: -; ThermalTransmittance: 0 W/K/m2; Reference: Reference
a-sh Abschluss Abhangdecke | H2 Ebene +2 | CEILING |  | 1216HWa0813303733 | m² |  |  |  |  |  | Gesamtwand |  |  |  | NEW | AllplanAttributes - Bezeichnung: a-sh Abschluss Abhangdecke; Attributset-Objekt: Covering; Object Layer Attributes #1, 2D Interaktion: yes; Object Layer Attributes #1, Gewerk: Trockenbauarbeiten; Object Layer Attributes #1, Material: A; Object Layer Attributes #1, Attributset-Objekt: Covering; Object Layer Attributes #1, Allright_Bauteil_ID: 1216Wa 0813302921; Object Layer Attributes #1, Abrechnungsart: m²; Object Layer Attributes #1, Objektname: Wand; Object Layer Attributes #1, Bezeichnung: a-sh Abschluss Abhangdecke; Pset_CoveringCommon - IsExternal: no; FireRating: -; ThermalTransmittance: 0 W/K/m2; Reference: Reference
a-sh Abschluss Abhangdecke | H2 Ebene +2 | CEILING |  | 1216HWa0813303735 | m² |  |  |  |  |  | Gesamtwand |  |  |  | NEW | AllplanAttributes - Bezeichnung: a-sh Abschluss Abhangdecke; Attributset-Objekt: Covering; Object Layer Attributes #1, 2D Interaktion: yes; Object Layer Attributes #1, Gewerk: Trockenbauarbeiten; Object Layer Attributes #1, Material: A; Object Layer Attributes #1, Attributset-Objekt: Covering; Object Layer Attributes #1, Allright_Bauteil_ID: 1216Wa 0813302923; Object Layer Attributes #1, Abrechnungsart: m²; Object Layer Attributes #1, Objektname: Wand; Object Layer Attributes #1, Bezeichnung: a-sh Abschluss Abhangdecke; Pset_CoveringCommon - IsExternal: no; FireRating: -; ThermalTransmittance: 0 W/K/m2; Reference: Reference
a-sh Abschluss Abhangdecke | H2 Ebene +2 | CEILING |  | 1216HWa0813303737 | m² |  |  |  |  |  | Gesamtwand |  |  |  | NEW | AllplanAttributes - Bezeichnung: a-sh Abschluss Abhangdecke; Attributset-Objekt: Covering; Object Layer Attributes #1, 2D Interaktion: yes; Object Layer Attributes #1, Gewerk: Trockenbauarbeiten; Object Layer Attributes #1, Material: A; Object Layer Attributes #1, Attributset-Objekt: Covering; Object Layer Attributes #1, Allright_Bauteil_ID: 1216Wa 0813302925; Object Layer Attributes #1, Abrechnungsart: m²; Object Layer Attributes #1, Objektname: Wand; Object Layer Attributes #1, Bezeichnung: a-sh Abschluss Abhangdecke; Pset_CoveringCommon - IsExternal: no; FireRating: -; ThermalTransmittance: 0 W/K/m2; Reference: Reference
a-sh Abschluss Abhangdecke | H2 Ebene +2 | CEILING |  | 1216HWa0813303739 | m² |  |  |  |  |  | Gesamtwand |  |  |  | NEW | AllplanAttributes - Bezeichnung: a-sh Abschluss Abhangdecke; Attributset-Objekt: Covering; Object Layer Attributes #1, 2D Interaktion: yes; Object Layer Attributes #1, Gewerk: Trockenbauarbeiten; Object Layer Attributes #1, Material: A; Object Layer Attributes #1, Attributset-Objekt: Covering; Object Layer Attributes #1, Allright_Bauteil_ID: 1216Wa 0813302927; Object Layer Attributes #1, Abrechnungsart: m²; Object Layer Attributes #1, Objektname: Wand; Object Layer Attributes #1, Bezeichnung: a-sh Abschluss Abhangdecke; Pset_CoveringCommon - IsExternal: no; FireRating: -; ThermalTransmittance: 0 W/K/m2; Reference: Reference
a-sh Abschluss Abhangdecke | H2 Ebene +2 | CEILING |  | 1216HWa0813303741 | m² |  |  |  |  |  | Gesamtwand |  |  |  | NEW | AllplanAttributes - Bezeichnung: a-sh Abschluss Abhangdecke; Attributset-Objekt: Covering; Object Layer Attributes #1, 2D Interaktion: yes; Object Layer Attributes #1, Gewerk: Trockenbauarbeiten; Object Layer Attributes #1, Material: A; Object Layer Attributes #1, Attributset-Objekt: Covering; Object Layer Attributes #1, Allright_Bauteil_ID: 1216Wa 0813302929; Object Layer Attributes #1, Abrechnungsart: m²; Object Layer Attributes #1, Objektname: Wand; Object Layer Attributes #1, Bezeichnung: a-sh Abschluss Abhangdecke; Pset_CoveringCommon - IsExternal: no; FireRating: -; ThermalTransmittance: 0 W/K/m2; Reference: Reference
a-sh Abschluss Abhangdecke | H2 Ebene +2 | CEILING |  | 1216HWa0813303743 | m² |  |  |  |  |  | Gesamtwand |  |  |  | NEW | AllplanAttributes - Bezeichnung: a-sh Abschluss Abhangdecke; Attributset-Objekt: Covering; Object Layer Attributes #1, 2D Interaktion: yes; Object Layer Attributes #1, Gewerk: Trockenbauarbeiten; Object Layer Attributes #1, Material: A; Object Layer Attributes #1, Attributset-Objekt: Covering; Object Layer Attributes #1, Allright_Bauteil_ID: 1216Wa 0813302931; Object Layer Attributes #1, Abrechnungsart: m²; Object Layer Attributes #1, Objektname: Wand; Object Layer Attributes #1, Bezeichnung: a-sh Abschluss Abhangdecke; Pset_CoveringCommon - IsExternal: no; FireRating: -; ThermalTransmittance: 0 W/K/m2; Reference: Reference
a-sh Abschluss Abhangdecke | H2 Ebene +2 | CEILING |  | 1216HWa0813303745 | m² |  |  |  |  |  | Gesamtwand |  |  |  | NEW | AllplanAttributes - Bezeichnung: a-sh Abschluss Abhangdecke; Attributset-Objekt: Covering; Object Layer Attributes #1, 2D Interaktion: yes; Object Layer Attributes #1, Gewerk: Trockenbauarbeiten; Object Layer Attributes #1, Material: A; Object Layer Attributes #1, Attributset-Objekt: Covering; Object Layer Attributes #1, Allright_Bauteil_ID: 1216Wa 0813302933; Object Layer Attributes #1, Abrechnungsart: m²; Object Layer Attributes #1, Objektname: Wand; Object Layer Attributes #1, Bezeichnung: a-sh Abschluss Abhangdecke; Pset_CoveringCommon - IsExternal: no; FireRating: -; ThermalTransmittance: 0 W/K/m2; Reference: Reference
a-sh Abschluss Abhangdecke | H2 Ebene +2 | CEILING |  | 1216HWa0813303747 | m² |  |  |  |  |  | Gesamtwand |  |  |  | NEW | AllplanAttributes - Bezeichnung: a-sh Abschluss Abhangdecke; Attributset-Objekt: Covering; Object Layer Attributes #1, 2D Interaktion: yes; Object Layer Attributes #1, Gewerk: Trockenbauarbeiten; Object Layer Attributes #1, Material: A; Object Layer Attributes #1, Attributset-Objekt: Covering; Object Layer Attributes #1, Allright_Bauteil_ID: 1216Wa 0813302935; Object Layer Attributes #1, Abrechnungsart: m²; Object Layer Attributes #1, Objektname: Wand; Object Layer Attributes #1, Bezeichnung: a-sh Abschluss Abhangdecke; Pset_CoveringCommon - IsExternal: no; FireRating: -; ThermalTransmittance: 0 W/K/m2; Reference: Reference
a-sh Abschluss Abhangdecke | H2 Ebene +2 | CEILING |  | 1216HWa0813303749 | m² |  |  |  |  |  | Gesamtwand |  |  |  | NEW | AllplanAttributes - Bezeichnung: a-sh Abschluss Abhangdecke; Attributset-Objekt: Covering; Object Layer Attributes #1, 2D Interaktion: yes; Object Layer Attributes #1, Gewerk: Trockenbauarbeiten; Object Layer Attributes #1, Material: A; Object Layer Attributes #1, Attributset-Objekt: Covering; Object Layer Attributes #1, Allright_Bauteil_ID: 1216Wa 0813302937; Object Layer Attributes #1, Abrechnungsart: m²; Object Layer Attributes #1, Objektname: Wand; Object Layer Attributes #1, Bezeichnung: a-sh Abschluss Abhangdecke; Pset_CoveringCommon - IsExternal: no; FireRating: -; ThermalTransmittance: 0 W/K/m2; Reference: Reference
a-sh Abschluss Abhangdecke | H2 Ebene +2 | CEILING |  | 1216HWa0813303751 | m² |  |  |  |  |  | Gesamtwand |  |  |  | NEW | AllplanAttributes - Bezeichnung: a-sh Abschluss Abhangdecke; Attributset-Objekt: Covering; Object Layer Attributes #1, 2D Interaktion: yes; Object Layer Attributes #1, Gewerk: Trockenbauarbeiten; Object Layer Attributes #1, Material: A; Object Layer Attributes #1, Attributset-Objekt: Covering; Object Layer Attributes #1, Allright_Bauteil_ID: 1216Wa 0813302939; Object Layer Attributes #1, Abrechnungsart: m²; Object Layer Attributes #1, Objektname: Wand; Object Layer Attributes #1, Bezeichnung: a-sh Abschluss Abhangdecke; Pset_CoveringCommon - IsExternal: no; FireRating: -; ThermalTransmittance: 0 W/K/m2; Reference: Reference
a-sh Abschluss Abhangdecke | H2 Ebene +2 | CEILING |  | 1216HWa0813303753 | m² |  |  |  |  |  | Gesamtwand |  |  |  | NEW | AllplanAttributes - Bezeichnung: a-sh Abschluss Abhangdecke; Attributset-Objekt: Covering; Object Layer Attributes #1, 2D Interaktion: yes; Object Layer Attributes #1, Gewerk: Trockenbauarbeiten; Object Layer Attributes #1, Material: A; Object Layer Attributes #1, Attributset-Objekt: Covering; Object Layer Attributes #1, Allright_Bauteil_ID: 1216Wa 0813302941; Object Layer Attributes #1, Abrechnungsart: m²; Object Layer Attributes #1, Objektname: Wand; Object Layer Attributes #1, Bezeichnung: a-sh Abschluss Abhangdecke; Pset_CoveringCommon - IsExternal: no; FireRating: -; ThermalTransmittance: 0 W/K/m2; Reference: Reference
a-sh Abschluss Abhangdecke | H2 Ebene +2 | CEILING |  | 1216HWa0813303755 | m² |  |  |  |  |  | Gesamtwand |  |  |  | NEW | AllplanAttributes - Bezeichnung: a-sh Abschluss Abhangdecke; Attributset-Objekt: Covering; Object Layer Attributes #1, 2D Interaktion: yes; Object Layer Attributes #1, Gewerk: Trockenbauarbeiten; Object Layer Attributes #1, Material: A; Object Layer Attributes #1, Attributset-Objekt: Covering; Object Layer Attributes #1, Allright_Bauteil_ID: 1216Wa 0813302943; Object Layer Attributes #1, Abrechnungsart: m²; Object Layer Attributes #1, Objektname: Wand; Object Layer Attributes #1, Bezeichnung: a-sh Abschluss Abhangdecke; Pset_CoveringCommon - IsExternal: no; FireRating: -; ThermalTransmittance: 0 W/K/m2; Reference: Reference
a-sh Abschluss Abhangdecke | H2 Ebene +2 | CEILING |  | 1216HWa0813303757 | m² |  |  |  |  |  | Gesamtwand |  |  |  | NEW | AllplanAttributes - Bezeichnung: a-sh Abschluss Abhangdecke; Attributset-Objekt: Covering; Object Layer Attributes #1, 2D Interaktion: yes; Object Layer Attributes #1, Gewerk: Trockenbauarbeiten; Object Layer Attributes #1, Material: A; Object Layer Attributes #1, Attributset-Objekt: Covering; Object Layer Attributes #1, Allright_Bauteil_ID: 1216Wa 0813302945; Object Layer Attributes #1, Abrechnungsart: m²; Object Layer Attributes #1, Objektname: Wand; Object Layer Attributes #1, Bezeichnung: a-sh Abschluss Abhangdecke; Pset_CoveringCommon - IsExternal: no; FireRating: -; ThermalTransmittance: 0 W/K/m2; Reference: Reference
a-sh Abschluss Abhangdecke | H2 Ebene +2 | CEILING |  | 1216HWa0813303759 | m² |  |  |  |  |  | Gesamtwand |  |  |  | NEW | AllplanAttributes - Bezeichnung: a-sh Abschluss Abhangdecke; Attributset-Objekt: Covering; Object Layer Attributes #1, 2D Interaktion: yes; Object Layer Attributes #1, Gewerk: Trockenbauarbeiten; Object Layer Attributes #1, Material: A; Object Layer Attributes #1, Attributset-Objekt: Covering; Object Layer Attributes #1, Allright_Bauteil_ID: 1216Wa 0813302947; Object Layer Attributes #1, Abrechnungsart: m²; Object Layer Attributes #1, Objektname: Wand; Object Layer Attributes #1, Bezeichnung: a-sh Abschluss Abhangdecke; Pset_CoveringCommon - IsExternal: no; FireRating: -; ThermalTransmittance: 0 W/K/m2; Reference: Reference
a-sh Abschluss Abhangdecke | H2 Ebene +2 | CEILING |  | 1216HWa0813303761 | m² |  |  |  |  |  | Gesamtwand |  |  |  | NEW | AllplanAttributes - Bezeichnung: a-sh Abschluss Abhangdecke; Attributset-Objekt: Covering; Object Layer Attributes #1, 2D Interaktion: yes; Object Layer Attributes #1, Gewerk: Trockenbauarbeiten; Object Layer Attributes #1, Material: A; Object Layer Attributes #1, Attributset-Objekt: Covering; Object Layer Attributes #1, Allright_Bauteil_ID: 1216Wa 0813302949; Object Layer Attributes #1, Abrechnungsart: m²; Object Layer Attributes #1, Objektname: Wand; Object Layer Attributes #1, Bezeichnung: a-sh Abschluss Abhangdecke; Pset_CoveringCommon - IsExternal: no; FireRating: -; ThermalTransmittance: 0 W/K/m2; Reference: Reference
a-sh Abschluss Abhangdecke | H2 Ebene +2 | CEILING |  | 1216HWa0813303763 | m² |  |  |  |  |  | Gesamtwand |  |  |  | NEW | AllplanAttributes - Bezeichnung: a-sh Abschluss Abhangdecke; Attributset-Objekt: Covering; Object Layer Attributes #1, 2D Interaktion: yes; Object Layer Attributes #1, Gewerk: Trockenbauarbeiten; Object Layer Attributes #1, Material: A; Object Layer Attributes #1, Attributset-Objekt: Covering; Object Layer Attributes #1, Allright_Bauteil_ID: 1216Wa 0813302951; Object Layer Attributes #1, Abrechnungsart: m²; Object Layer Attributes #1, Objektname: Wand; Object Layer Attributes #1, Bezeichnung: a-sh Abschluss Abhangdecke; Pset_CoveringCommon - IsExternal: no; FireRating: -; ThermalTransmittance: 0 W/K/m2; Reference: Reference
a-sh Abschluss Abhangdecke | H2 Ebene +2 | CEILING |  | 1216HWa0813303765 | m² |  |  |  |  |  | Gesamtwand |  |  |  | NEW | AllplanAttributes - Bezeichnung: a-sh Abschluss Abhangdecke; Attributset-Objekt: Covering; Object Layer Attributes #1, 2D Interaktion: yes; Object Layer Attributes #1, Gewerk: Trockenbauarbeiten; Object Layer Attributes #1, Material: A; Object Layer Attributes #1, Attributset-Objekt: Covering; Object Layer Attributes #1, Allright_Bauteil_ID: 1216Wa 0813302953; Object Layer Attributes #1, Abrechnungsart: m²; Object Layer Attributes #1, Objektname: Wand; Object Layer Attributes #1, Bezeichnung: a-sh Abschluss Abhangdecke; Pset_CoveringCommon - IsExternal: no; FireRating: -; ThermalTransmittance: 0 W/K/m2; Reference: Reference
a-sh Abschluss Abhangdecke | H2 Ebene +2 | CEILING |  | 1216HWa0813303767 | m² |  |  |  |  |  | Gesamtwand |  |  |  | NEW | AllplanAttributes - Bezeichnung: a-sh Abschluss Abhangdecke; Attributset-Objekt: Covering; Object Layer Attributes #1, 2D Interaktion: yes; Object Layer Attributes #1, Gewerk: Trockenbauarbeiten; Object Layer Attributes #1, Material: A; Object Layer Attributes #1, Attributset-Objekt: Covering; Object Layer Attributes #1, Allright_Bauteil_ID: 1216Wa 0813302955; Object Layer Attributes #1, Abrechnungsart: m²; Object Layer Attributes #1, Objektname: Wand; Object Layer Attributes #1, Bezeichnung: a-sh Abschluss Abhangdecke; Pset_CoveringCommon - IsExternal: no; FireRating: -; ThermalTransmittance: 0 W/K/m2; Reference: Reference
a-sh Abschluss Abhangdecke | H2 Ebene +2 | CEILING |  | 1216HWa0813303769 | m² |  |  |  |  |  | Gesamtwand |  |  |  | NEW | AllplanAttributes - Bezeichnung: a-sh Abschluss Abhangdecke; Attributset-Objekt: Covering; Object Layer Attributes #1, 2D Interaktion: yes; Object Layer Attributes #1, Gewerk: Trockenbauarbeiten; Object Layer Attributes #1, Material: A; Object Layer Attributes #1, Attributset-Objekt: Covering; Object Layer Attributes #1, Allright_Bauteil_ID: 1216Wa 0813302957; Object Layer Attributes #1, Abrechnungsart: m²; Object Layer Attributes #1, Objektname: Wand; Object Layer Attributes #1, Bezeichnung: a-sh Abschluss Abhangdecke; Pset_CoveringCommon - IsExternal: no; FireRating: -; ThermalTransmittance: 0 W/K/m2; Reference: Reference
a-sh Abschluss Abhangdecke | H2 Ebene +2 | CEILING |  | 1216HWa0813303771 | m² |  |  |  |  |  | Gesamtwand |  |  |  | NEW | AllplanAttributes - Bezeichnung: a-sh Abschluss Abhangdecke; Attributset-Objekt: Covering; Object Layer Attributes #1, 2D Interaktion: yes; Object Layer Attributes #1, Gewerk: Trockenbauarbeiten; Object Layer Attributes #1, Material: A; Object Layer Attributes #1, Attributset-Objekt: Covering; Object Layer Attributes #1, Allright_Bauteil_ID: 1216Wa 0813302959; Object Layer Attributes #1, Abrechnungsart: m²; Object Layer Attributes #1, Objektname: Wand; Object Layer Attributes #1, Bezeichnung: a-sh Abschluss Abhangdecke; Pset_CoveringCommon - IsExternal: no; FireRating: -; ThermalTransmittance: 0 W/K/m2; Reference: Reference
a-sh Abschluss Abhangdecke | H2 Ebene +2 | CEILING |  | 1216HWa0813303773 | m² |  |  |  |  |  | Gesamtwand |  |  |  | NEW | AllplanAttributes - Bezeichnung: a-sh Abschluss Abhangdecke; Attributset-Objekt: Covering; Object Layer Attributes #1, 2D Interaktion: yes; Object Layer Attributes #1, Gewerk: Trockenbauarbeiten; Object Layer Attributes #1, Material: A; Object Layer Attributes #1, Attributset-Objekt: Covering; Object Layer Attributes #1, Allright_Bauteil_ID: 1216Wa 0813302961; Object Layer Attributes #1, Abrechnungsart: m²; Object Layer Attributes #1, Objektname: Wand; Object Layer Attributes #1, Bezeichnung: a-sh Abschluss Abhangdecke; Pset_CoveringCommon - IsExternal: no; FireRating: -; ThermalTransmittance: 0 W/K/m2; Reference: Reference
Fliesen Großformat | H2 Ebene +2 | FLOORING | Fl12 0.1 m | 1216Bfl0812907719/01 | m² | Bodenbelagsarbeiten | 1 | 0.1 | 0 | 1 | Bodenfläche | Fl12 | 0 | 0 | NEW | AllplanAttributes - Bezeichnung: Fliesen Großformat; ash B_Aufbau: B7; ash B_Rutschhemmung: R10
Fliesen Großformat | H2 Ebene +2 | FLOORING | Fl12 0.15 m | 1216Bfl0812907367/01 | m² | Bodenbelagsarbeiten | 1 | 0.15 | 0 | 1 | Bodenfläche | Fl12 | 0 | 0 | NEW | AllplanAttributes - Bezeichnung: Fliesen Großformat; Raumnr. Bauherr: B8; ash B_Rutschhemmung: R10
PVC Bahnenware Holzoptik | WUN-H2-E02-008 | FLOORING | Ku1 0.15 m | 1216Bfl0000046476/01 | m² | Bodenbelagsarbeiten | 1 | 0.15 | 0 | 1 | Bodenfläche | Ku1 | 0 | 0 | NEW | AllplanAttributes - Bezeichnung: PVC Bahnenware Holzoptik; Raumnr. Bauherr: 2.11_A2_02; ash B_Aufbau: B9; ash B_Rutschhemmung: R9
Gipsfaserplatten 2-lagig (BSK) | WUN-H2-E02-008 | CEILING | layer 0.036 m | 1216Dfl0812905458/01 | m² | Trockenbauarbeiten | 1 | 0.036 | 0 | 1 | Deckenfläche |  | 0 | 0 | NEW | 2.75 | AllplanAttributes - Bezeichnung: Gipsfaserplatten 2-lagig (BSK); ash_lichte Raumhöhe: 2.75
 | WUN-H2-E02-008 | CEILING | Installationshöhe 0.424 m | 1216Dfl0812905458/02 | m² | Trockenbauarbeiten | 2 | 0.424 | 0 | 1 | Bekleidung | Installationshöhe | 0 | 0 | NEW
 | WUN-H2-E02-008 | CEILING | Aa 0.15 m | 1216Dfl0812905458/03 | m² | Trockenbauarbeiten | 3 | 0.15 | 0 | 1 | Bekleidung | Aa | 0 | 0 | NEW | Pset_CoveringCommon - AcousticRating: -
 | WUN-H2-E02-008 | CEILING | D1 0.001 m | 1216Dfl0812905458/04 | m² | Maler- und Lackierarbeiten | 4 | 0.001 | 0 | 1 | Bekleidung | D1 | 0 | 0 | NEW
Gipsfaserplatten 2-lagig (BSK) | WUN-H2-E02-008 | CEILING | layer 0.036 m | 1216Dfl0812906259/01 | m² | Trockenbauarbeiten | 1 | 0.036 | 0 | 1 | Deckenfläche |  | 0 | 0 | NEW | 3.1 | AllplanAttributes - Bezeichnung: Gipsfaserplatten 2-lagig (BSK); ash_lichte Raumhöhe: 3.1
 | WUN-H2-E02-008 | CEILING | Installationshöhe 0.124 m | 1216Dfl0812906259/02 | m² | Trockenbauarbeiten | 2 | 0.124 | 0 | 1 | Bekleidung | Installationshöhe | 0 | 0 | NEW
 | WUN-H2-E02-008 | CEILING | A1 0.1 m | 1216Dfl0812906259/03 | m² | Trockenbauarbeiten | 3 | 0.1 | 0 | 1 | Bekleidung | A1 | 0 | 0 | NEW | Pset_CoveringCommon - AcousticRating: -
 | WUN-H2-E02-008 | CEILING | D1 0.001 m | 1216Dfl0812906259/04 | m² | Maler- und Lackierarbeiten | 4 | 0.001 | 0 | 1 | Bekleidung | D1 | 0 | 0 | NEW
Gipsfaserplatten 2-lagig (BSK) | WUN-H2-E02-008 | CEILING | layer 0.036 m | 1216Dfl0812906250/01 | m² | Trockenbauarbeiten | 1 | 0.036 | 0 | 1 | Deckenfläche |  | 0 | 0 | NEW | 2.75 | AllplanAttributes - Bezeichnung: Gipsfaserplatten 2-lagig (BSK); ash_lichte Raumhöhe: 2.75
 | WUN-H2-E02-008 | CEILING | Installationshöhe 0.464 m | 1216Dfl0812906250/02 | m² | Trockenbauarbeiten | 2 | 0.464 | 0 | 1 | Bekleidung | Installationshöhe | 0 | 0 | NEW
 | WUN-H2-E02-008 | CEILING | Aa 0.15 m | 1216Dfl0812906250/03 | m² | Trockenbauarbeiten | 3 | 0.15 | 0 | 1 | Bekleidung | Aa | 0 | 0 | NEW | Pset_CoveringCommon - AcousticRating: -
 | WUN-H2-E02-008 | CEILING | D1 0.001 m | 1216Dfl0812906250/04 | m² | Maler- und Lackierarbeiten | 4 | 0.001 | 0 | 1 | Bekleidung | D1 | 0 | 0 | NEW
Gipsfaserplatten 2-lagig (BSK) | WUN-H2-E02-008 | CEILING | layer 0.036 m | 1216Dfl0812905457/01 | m² | Trockenbauarbeiten | 1 | 0.036 | 0 | 1 | Deckenfläche |  | 0 | 0 | NEW | 2.75 | AllplanAttributes - Bezeichnung: Gipsfaserplatten 2-lagig (BSK); ash_lichte Raumhöhe: 2.75
 | WUN-H2-E02-008 | CEILING | Installationshöhe 0.424 m | 1216Dfl0812905457/02 | m² | Trockenbauarbeiten | 2 | 0.424 | 0 | 1 | Bekleidung | Installationshöhe | 0 | 0 | NEW
 | WUN-H2-E02-008 | CEILING | A1 0.15 m | 1216Dfl0812905457/03 | m² | Trockenbauarbeiten | 3 | 0.15 | 0 | 1 | Bekleidung | A1 | 0 | 0 | NEW | Pset_CoveringCommon - AcousticRating: -
 | WUN-H2-E02-008 | CEILING | D1 0.001 m | 1216Dfl0812905457/04 | m² | Maler- und Lackierarbeiten | 4 | 0.001 | 0 | 1 | Bekleidung | D1 | 0 | 0 | NEW
Gipsfaserplatten 2-lagig (BSK) | WUN-H2-E02-008 | CEILING | layer 0.036 m | 1216Dfl0000046477/01 | m² | Trockenbauarbeiten | 1 | 0.036 | 0 | 1 | Deckenfläche |  | 0 | 0 | NEW | 3.15 | AllplanAttributes - Bezeichnung: Gipsfaserplatten 2-lagig (BSK); ash_lichte Raumhöhe: 3.1
 | WUN-H2-E02-008 | CEILING | Installationshöhe 0.164 m | 1216Dfl0000046477/02 | m² | Trockenbauarbeiten | 2 | 0.164 | 0 | 1 | Bekleidung | Installationshöhe | 0 | 0 | NEW | Pset_CoveringCommon - AcousticRating: -
 | WUN-H2-E02-008 | CEILING | A1 0.1 m | 1216Dfl0000046477/03 | m² | Trockenbauarbeiten | 3 | 0.1 | 0 | 1 | Bekleidung | A1 | 0 | 0 | NEW | Pset_CoveringCommon - AcousticRating: -
 | WUN-H2-E02-008 | CEILING | D1 0.001 m | 1216Dfl0000046477/04 | m² | Maler- und Lackierarbeiten | 4 | 0.001 | 0 | 1 | Bekleidung | D1 | 0 | 0 | NEW
Gipsfaserplatten 2-lagig (BSK) | WUN-H2-E02-008 | CEILING | layer 0.036 m | 1216Dfl0812906252/01 | m² | Trockenbauarbeiten | 1 | 0.036 | 0 | 1 | Deckenfläche |  | 0 | 0 | NEW | 2.75 | AllplanAttributes - Bezeichnung: Gipsfaserplatten 2-lagig (BSK); ash_lichte Raumhöhe: 2.75
 | WUN-H2-E02-008 | CEILING | Installationshöhe 0.464 m | 1216Dfl0812906252/02 | m² | Trockenbauarbeiten | 2 | 0.464 | 0 | 1 | Bekleidung | Installationshöhe | 0 | 0 | NEW
 | WUN-H2-E02-008 | CEILING | A1 0.15 m | 1216Dfl0812906252/03 | m² | Trockenbauarbeiten | 3 | 0.15 | 0 | 1 | Bekleidung | A1 | 0 | 0 | NEW | Pset_CoveringCommon - AcousticRating: -
 | WUN-H2-E02-008 | CEILING | D1 0.001 m | 1216Dfl0812906252/04 | m² | Maler- und Lackierarbeiten | 4 | 0.001 | 0 | 1 | Bekleidung | D1 | 0 | 0 | NEW
PVC Bahnenware Holzoptik | WUN-H2-E02-050 | FLOORING | Ku1 0.15 m | 1216Bfl0000047214/01 | m² | Bodenbelagsarbeiten | 1 | 0.15 | 0 | 1 | Bodenfläche | Ku1 | 0 | 0 | NEW | AllplanAttributes - Bezeichnung: PVC Bahnenware Holzoptik; Raumnr. Bauherr: 2.11_A2_02; ash B_Aufbau: B9; ash B_Rutschhemmung: R9
Gipsfaserplatten 2-lagig (BSK) | WUN-H2-E02-050 | CEILING | layer 0.036 m | 1216Dfl0000047215/01 | m² | Trockenbauarbeiten | 1 | 0.036 | 0 | 1 | Deckenfläche |  | 0 | 0 | NEW | 3.15 | AllplanAttributes - Bezeichnung: Gipsfaserplatten 2-lagig (BSK); ash_lichte Raumhöhe: 3.1
 | WUN-H2-E02-050 | CEILING | Installationshöhe 0.124 m | 1216Dfl0000047215/02 | m² | Trockenbauarbeiten | 2 | 0.124 | 0 | 1 | Bekleidung | Installationshöhe | 0 | 0 | NEW | Pset_CoveringCommon - AcousticRating: -
 | WUN-H2-E02-050 | CEILING | A1 0.1 m | 1216Dfl0000047215/03 | m² | Trockenbauarbeiten | 3 | 0.1 | 0 | 1 | Bekleidung | A1 | 0 | 0 | NEW | Pset_CoveringCommon - AcousticRating: -
 | WUN-H2-E02-050 | CEILING | D1 0.001 m | 1216Dfl0000047215/04 | m² | Maler- und Lackierarbeiten | 4 | 0.001 | 0 | 1 | Bekleidung | D1 | 0 | 0 | NEW
Gipsfaserplatten 2-lagig (BSK) | WUN-H2-E02-050 | CEILING | layer 0.036 m | 1216Dfl0000047226/01 | m² | Trockenbauarbeiten | 1 | 0.036 | 0 | 1 | Deckenfläche |  | 0 | 0 | NEW | 2.5 | AllplanAttributes - Bezeichnung: Gipsfaserplatten 2-lagig (BSK); ash_lichte Raumhöhe: 2.5
 | WUN-H2-E02-050 | CEILING | Installationshöhe 0.724 m | 1216Dfl0000047226/02 | m² | Trockenbauarbeiten | 2 | 0.724 | 0 | 1 | Bekleidung | Installationshöhe | 0 | 0 | NEW | AllplanAttributes - OKFF: 0
 | WUN-H2-E02-050 | CEILING | A1 0.1 m | 1216Dfl0000047226/03 | m² | Trockenbauarbeiten | 3 | 0.1 | 0 | 1 | Bekleidung | A1 | 0 | 0 | NEW | Pset_CoveringCommon - AcousticRating: -; AllplanAttributes - OKFF: 0
 | WUN-H2-E02-050 | CEILING | D1 0.001 m | 1216Dfl0000047226/04 | m² | Maler- und Lackierarbeiten | 4 | 0.001 | 0 | 1 | Bekleidung | D1 | 0 | 0 | NEW | AllplanAttributes - OKFF: 0
UK+Estrich | WUN-H2-E02-L02 | FLOORING | layer 0.25 m | 1216Bfl0812993950/01 | m² | Bodenbelagsarbeiten | 1 | 0.25 | 0 | 1 | Bodenfläche |  | 0 | 0 | NEW | AllplanAttributes - Bezeichnung: UK+Estrich; Raumnr. Bauherr: 2.11_A2_02
Feinsteinzeugplatten 40x40x3 | WUN-H2-E02-L02 | FLOORING | FP2 0.03 m | 1216Bfl0812993950/02 | m² | Bodenbelagsarbeiten | 2 | 0.03 | 0 | 1 | Bodenfläche | FP2 | 0 | 0 | NEW | AllplanAttributes - Bezeichnung: Feinsteinzeugplatten 40x40x3
 | WUN-H2-E02-L02 | CEILING | Installationshöhe 0.18 m | 1216Dfl0812993949/01 | m² | Trockenbauarbeiten | 1 | 0.18 | 0 | 1 | Bekleidung | Installationshöhe | 0 | 0 | NEW | 3.15 | AllplanAttributes - ash_lichte Raumhöhe: 3.095; Pset_CoveringCommon - AcousticRating: -
 | WUN-H2-E02-L02 | CEILING | - 0.045 m | 1216Dfl0812993949/02 | m² | Trockenbauarbeiten | 2 | 0.045 | 0 | 1 | Bekleidung | - | 0 | 0 | NEW | Pset_CoveringCommon - AcousticRating: -
UK+Estrich | WUN-H2-E02-L01 | FLOORING | layer 0.25 m | 1216Bfl0812993952/01 | m² | Bodenbelagsarbeiten | 1 | 0.25 | 0 | 1 | Bodenfläche |  | 0 | 0 | NEW | AllplanAttributes - Bezeichnung: UK+Estrich; Raumnr. Bauherr: 2.11_A2_02
Feinsteinzeugplatten 40x40x3 | WUN-H2-E02-L01 | FLOORING | FP2 0.03 m | 1216Bfl0812993952/02 | m² | Bodenbelagsarbeiten | 2 | 0.03 | 0 | 1 | Bodenfläche | FP2 | 0 | 0 | NEW | AllplanAttributes - Bezeichnung: Feinsteinzeugplatten 40x40x3
 | WUN-H2-E02-L01 | CEILING | Installationshöhe 0.18 m | 1216Dfl0812993951/01 | m² | Trockenbauarbeiten | 1 | 0.18 | 0 | 1 | Bekleidung | Installationshöhe | 0 | 0 | NEW | 3.15 | AllplanAttributes - ash_lichte Raumhöhe: 3.095; Pset_CoveringCommon - AcousticRating: -
 | WUN-H2-E02-L01 | CEILING | - 0.045 m | 1216Dfl0812993951/02 | m² | Trockenbauarbeiten | 2 | 0.045 | 0 | 1 | Bekleidung | - | 0 | 0 | NEW | Pset_CoveringCommon - AcousticRating: -
PVC Bahnenware Holzoptik | WUN-H2-E02-048 | FLOORING | Ku1 0.15 m | 1216Bfl0000046490/01 | m² | Bodenbelagsarbeiten | 1 | 0.15 | 0 | 1 | Bodenfläche | Ku1 | 0 | 0 | NEW | AllplanAttributes - Bezeichnung: PVC Bahnenware Holzoptik; Raumnr. Bauherr: 2.11_A2_02; ash B_Aufbau: B9; ash B_Rutschhemmung: R9
Gipsfaserplatten 2-lagig (BSK) | WUN-H2-E02-048 | CEILING | layer 0.036 m | 1216Dfl0000046491/01 | m² | Trockenbauarbeiten | 1 | 0.036 | 0 | 1 | Deckenfläche |  | 0 | 0 | NEW | 3.15 | AllplanAttributes - Bezeichnung: Gipsfaserplatten 2-lagig (BSK); ash_lichte Raumhöhe: 3.1
 | WUN-H2-E02-048 | CEILING | Installationshöhe 0.124 m | 1216Dfl0000046491/02 | m² | Trockenbauarbeiten | 2 | 0.124 | 0 | 1 | Bekleidung | Installationshöhe | 0 | 0 | NEW | Pset_CoveringCommon - AcousticRating: -
 | WUN-H2-E02-048 | CEILING | A1 0.1 m | 1216Dfl0000046491/03 | m² | Trockenbauarbeiten | 3 | 0.1 | 0 | 1 | Bekleidung | A1 | 0 | 0 | NEW | Pset_CoveringCommon - AcousticRating: -
 | WUN-H2-E02-048 | CEILING | D1 0.001 m | 1216Dfl0000046491/04 | m² | Maler- und Lackierarbeiten | 4 | 0.001 | 0 | 1 | Bekleidung | D1 | 0 | 0 | NEW
Gipsfaserplatten 2-lagig (BSK) | WUN-H2-E02-048 | CEILING | layer 0.036 m | 1216Dfl0000046502/01 | m² | Trockenbauarbeiten | 1 | 0.036 | 0 | 1 | Deckenfläche |  | 0 | 0 | NEW | 2.5 | AllplanAttributes - Bezeichnung: Gipsfaserplatten 2-lagig (BSK); ash_lichte Raumhöhe: 2.5
 | WUN-H2-E02-048 | CEILING | Installationshöhe 0.724 m | 1216Dfl0000046502/02 | m² | Trockenbauarbeiten | 2 | 0.724 | 0 | 1 | Bekleidung | Installationshöhe | 0 | 0 | NEW | AllplanAttributes - OKFF: 0
 | WUN-H2-E02-048 | CEILING | A1 0.1 m | 1216Dfl0000046502/03 | m² | Trockenbauarbeiten | 3 | 0.1 | 0 | 1 | Bekleidung | A1 | 0 | 0 | NEW | Pset_CoveringCommon - AcousticRating: -; AllplanAttributes - OKFF: 0
 | WUN-H2-E02-048 | CEILING | D1 0.001 m | 1216Dfl0000046502/04 | m² | Maler- und Lackierarbeiten | 4 | 0.001 | 0 | 1 | Bekleidung | D1 | 0 | 0 | NEW | AllplanAttributes - OKFF: 0
PVC Bahnenware Holzoptik | WUN-H2-E02-055 | FLOORING | Ku1 0.15 m | 1216Bfl0000047200/01 | m² | Bodenbelagsarbeiten | 1 | 0.15 | 0 | 1 | Bodenfläche | Ku1 | 0 | 0 | NEW | AllplanAttributes - Bezeichnung: PVC Bahnenware Holzoptik; Raumnr. Bauherr: 2.11_A2_02; ash B_Aufbau: B9; ash B_Rutschhemmung: R9
Gipsfaserplatten 2-lagig (BSK) | WUN-H2-E02-055 | CEILING | layer 0.036 m | 1216Dfl0812883664/01 | m² | Trockenbauarbeiten | 1 | 0.036 | 0 | 1 | Deckenfläche |  | 0 | 0 | NEW | 2.75 | AllplanAttributes - Bezeichnung: Gipsfaserplatten 2-lagig (BSK); ash_lichte Raumhöhe: 2.75
 | WUN-H2-E02-055 | CEILING | Installationshöhe 0.464 m | 1216Dfl0812883664/02 | m² | Trockenbauarbeiten | 2 | 0.464 | 0 | 1 | Bekleidung | Installationshöhe | 0 | 0 | NEW
 | WUN-H2-E02-055 | CEILING | A1 0.15 m | 1216Dfl0812883664/03 | m² | Trockenbauarbeiten | 3 | 0.15 | 0 | 1 | Bekleidung | A1 | 0 | 0 | NEW | Pset_CoveringCommon - AcousticRating: -
 | WUN-H2-E02-055 | CEILING | D1 0.001 m | 1216Dfl0812883664/04 | m² | Maler- und Lackierarbeiten | 4 | 0.001 | 0 | 1 | Bekleidung | D1 | 0 | 0 | NEW
Gipsfaserplatten 2-lagig (BSK) | WUN-H2-E02-055 | CEILING | layer 0.036 m | 1216Dfl0812882870/01 | m² | Trockenbauarbeiten | 1 | 0.036 | 0 | 1 | Deckenfläche |  | 0 | 0 | NEW | 2.75 | AllplanAttributes - Bezeichnung: Gipsfaserplatten 2-lagig (BSK); ash_lichte Raumhöhe: 2.75
 | WUN-H2-E02-055 | CEILING | Installationshöhe 0.424 m | 1216Dfl0812882870/02 | m² | Trockenbauarbeiten | 2 | 0.424 | 0 | 1 | Bekleidung | Installationshöhe | 0 | 0 | NEW
 | WUN-H2-E02-055 | CEILING | Aa 0.15 m | 1216Dfl0812882870/03 | m² | Trockenbauarbeiten | 3 | 0.15 | 0 | 1 | Bekleidung | Aa | 0 | 0 | NEW | Pset_CoveringCommon - AcousticRating: -
 | WUN-H2-E02-055 | CEILING | D1 0.001 m | 1216Dfl0812882870/04 | m² | Maler- und Lackierarbeiten | 4 | 0.001 | 0 | 1 | Bekleidung | D1 | 0 | 0 | NEW
Gipsfaserplatten 2-lagig (BSK) | WUN-H2-E02-055 | CEILING | layer 0.036 m | 1216Dfl0812883662/01 | m² | Trockenbauarbeiten | 1 | 0.036 | 0 | 1 | Deckenfläche |  | 0 | 0 | NEW | 2.75 | AllplanAttributes - Bezeichnung: Gipsfaserplatten 2-lagig (BSK); ash_lichte Raumhöhe: 2.75
 | WUN-H2-E02-055 | CEILING | Installationshöhe 0.464 m | 1216Dfl0812883662/02 | m² | Trockenbauarbeiten | 2 | 0.464 | 0 | 1 | Bekleidung | Installationshöhe | 0 | 0 | NEW
 | WUN-H2-E02-055 | CEILING | Aa 0.15 m | 1216Dfl0812883662/03 | m² | Trockenbauarbeiten | 3 | 0.15 | 0 | 1 | Bekleidung | Aa | 0 | 0 | NEW | Pset_CoveringCommon - AcousticRating: -
 | WUN-H2-E02-055 | CEILING | D1 0.001 m | 1216Dfl0812883662/04 | m² | Maler- und Lackierarbeiten | 4 | 0.001 | 0 | 1 | Bekleidung | D1 | 0 | 0 | NEW
Gipsfaserplatten 2-lagig (BSK) | WUN-H2-E02-055 | CEILING | layer 0.036 m | 1216Dfl0812882869/01 | m² | Trockenbauarbeiten | 1 | 0.036 | 0 | 1 | Deckenfläche |  | 0 | 0 | NEW | 2.75 | AllplanAttributes - Bezeichnung: Gipsfaserplatten 2-lagig (BSK); ash_lichte Raumhöhe: 2.75
 | WUN-H2-E02-055 | CEILING | Installationshöhe 0.424 m | 1216Dfl0812882869/02 | m² | Trockenbauarbeiten | 2 | 0.424 | 0 | 1 | Bekleidung | Installationshöhe | 0 | 0 | NEW
 | WUN-H2-E02-055 | CEILING | A1 0.15 m | 1216Dfl0812882869/03 | m² | Trockenbauarbeiten | 3 | 0.15 | 0 | 1 | Bekleidung | A1 | 0 | 0 | NEW | Pset_CoveringCommon - AcousticRating: -
 | WUN-H2-E02-055 | CEILING | D1 0.001 m | 1216Dfl0812882869/04 | m² | Maler- und Lackierarbeiten | 4 | 0.001 | 0 | 1 | Bekleidung | D1 | 0 | 0 | NEW
Gipsfaserplatten 2-lagig (BSK) | WUN-H2-E02-055 | CEILING | layer 0.036 m | 1216Dfl0000047201/01 | m² | Trockenbauarbeiten | 1 | 0.036 | 0 | 1 | Deckenfläche |  | 0 | 0 | NEW | 3.15 | AllplanAttributes - Bezeichnung: Gipsfaserplatten 2-lagig (BSK); ash_lichte Raumhöhe: 3.1
 | WUN-H2-E02-055 | CEILING | Installationshöhe 0.164 m | 1216Dfl0000047201/02 | m² | Trockenbauarbeiten | 2 | 0.164 | 0 | 1 | Bekleidung | Installationshöhe | 0 | 0 | NEW | Pset_CoveringCommon - AcousticRating: -
 | WUN-H2-E02-055 | CEILING | A1 0.1 m | 1216Dfl0000047201/03 | m² | Trockenbauarbeiten | 3 | 0.1 | 0 | 1 | Bekleidung | A1 | 0 | 0 | NEW | Pset_CoveringCommon - AcousticRating: -
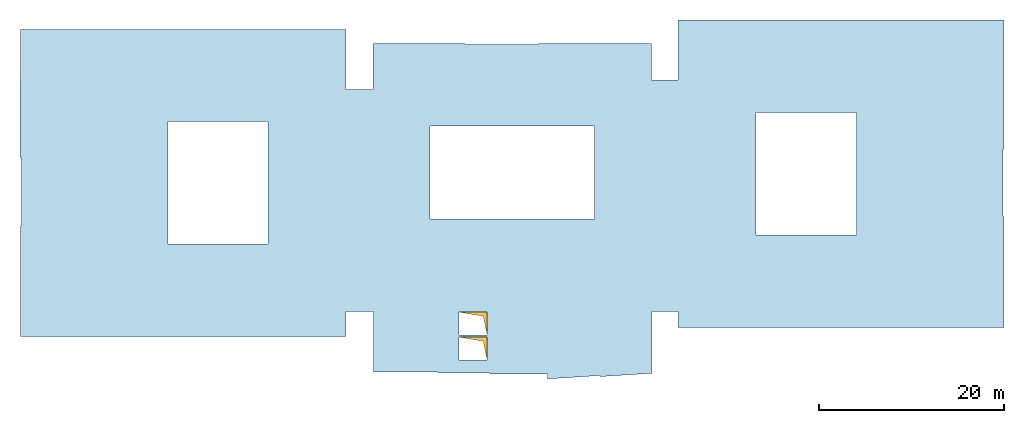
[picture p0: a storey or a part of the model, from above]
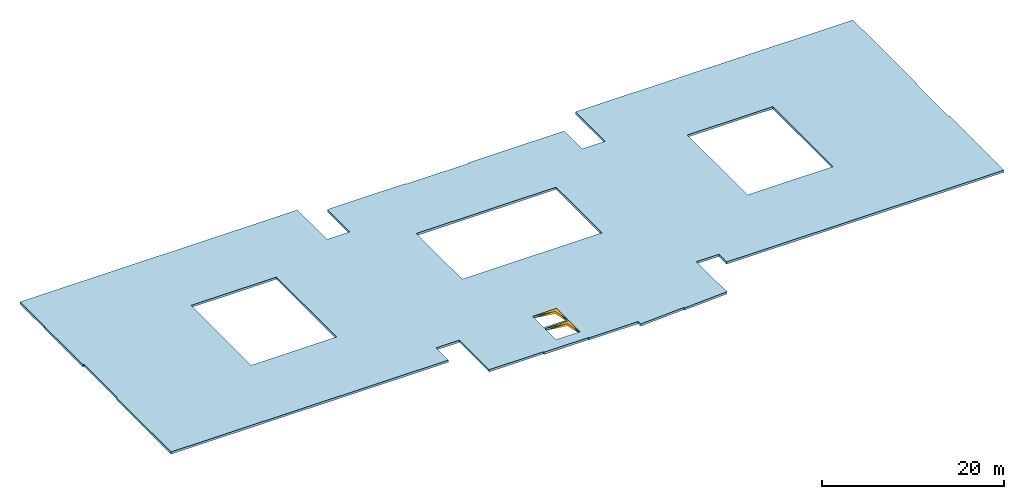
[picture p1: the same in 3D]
Properties of the parts of a building model (IFC4), part 7 of 80

# IfcCovering (3945)
Name | In | PredefinedType | Material | Allright_Bauteil_ID | Abrechnungsart | Gewerk | Schichtnummer | Schichtdicke (m) | Dicke (m) | Faktor | Objektname | AllplanAttributes, Material | Bezugshöhe | Deltahöhe | Status | D_lichte Raumhöhe [Zahl] (m)
 | WUN-H2-E02-055 | CEILING | D1 0.001 m | 1216Dfl0000047201/04 | m² | Maler- und Lackierarbeiten | 4 | 0.001 | 0 | 1 | Bekleidung | D1 | 0 | 0 | NEW
Gipsfaserplatten 2-lagig (BSK) | WUN-H2-E02-055 | CEILING | layer 0.036 m | 1216Dfl0812883670/01 | m² | Trockenbauarbeiten | 1 | 0.036 | 0 | 1 | Deckenfläche |  | 0 | 0 | NEW | 3.1 | AllplanAttributes - Bezeichnung: Gipsfaserplatten 2-lagig (BSK); ash_lichte Raumhöhe: 3.1
 | WUN-H2-E02-055 | CEILING | Installationshöhe 0.124 m | 1216Dfl0812883670/02 | m² | Trockenbauarbeiten | 2 | 0.124 | 0 | 1 | Bekleidung | Installationshöhe | 0 | 0 | NEW
 | WUN-H2-E02-055 | CEILING | A1 0.1 m | 1216Dfl0812883670/03 | m² | Trockenbauarbeiten | 3 | 0.1 | 0 | 1 | Bekleidung | A1 | 0 | 0 | NEW | Pset_CoveringCommon - AcousticRating: -
 | WUN-H2-E02-055 | CEILING | D1 0.001 m | 1216Dfl0812883670/04 | m² | Maler- und Lackierarbeiten | 4 | 0.001 | 0 | 1 | Bekleidung | D1 | 0 | 0 | NEW
PVC Bahnenware Holzoptik | WUN-H2-E02-060 | FLOORING | Ku1 0.15 m | 1216Bfl0000046772/01 | m² | Bodenbelagsarbeiten | 1 | 0.15 | 0 | 1 | Bodenfläche | Ku1 | 0 | 0 | NEW | AllplanAttributes - Bezeichnung: PVC Bahnenware Holzoptik; Raumnr. Bauherr: 2.11_A2_02; ash B_Aufbau: B9; ash B_Rutschhemmung: R9
Gipsfaserplatten 2-lagig (BSK) | WUN-H2-E02-060 | CEILING | layer 0.036 m | 1216Dfl0000046784/01 | m² | Trockenbauarbeiten | 1 | 0.036 | 0 | 1 | Deckenfläche |  | 0 | 0 | NEW | 2.5 | AllplanAttributes - Bezeichnung: Gipsfaserplatten 2-lagig (BSK); ash_lichte Raumhöhe: 2.5
 | WUN-H2-E02-060 | CEILING | Installationshöhe 0.714 m | 1216Dfl0000046784/02 | m² | Trockenbauarbeiten | 2 | 0.714 | 0 | 1 | Bekleidung | Installationshöhe | 0 | 0 | NEW | AllplanAttributes - OKFF: 0
 | WUN-H2-E02-060 | CEILING | A1 0.15 m | 1216Dfl0000046784/03 | m² | Trockenbauarbeiten | 3 | 0.15 | 0 | 1 | Bekleidung | A1 | 0 | 0 | NEW | Pset_CoveringCommon - AcousticRating: -; AllplanAttributes - OKFF: 0
 | WUN-H2-E02-060 | CEILING | D1 0.001 m | 1216Dfl0000046784/04 | m² | Maler- und Lackierarbeiten | 4 | 0.001 | 0 | 1 | Bekleidung | D1 | 0 | 0 | NEW | AllplanAttributes - OKFF: 0
Gipsfaserplatten 2-lagig (BSK) | WUN-H2-E02-060 | CEILING | layer 0.036 m | 1216Dfl0000046773/01 | m² | Trockenbauarbeiten | 1 | 0.036 | 0 | 1 | Deckenfläche |  | 0 | 0 | NEW | 3.15 | AllplanAttributes - Bezeichnung: Gipsfaserplatten 2-lagig (BSK); ash_lichte Raumhöhe: 3.1
 | WUN-H2-E02-060 | CEILING | Installationshöhe 0.164 m | 1216Dfl0000046773/02 | m² | Trockenbauarbeiten | 2 | 0.164 | 0 | 1 | Bekleidung | Installationshöhe | 0 | 0 | NEW | Pset_CoveringCommon - AcousticRating: -
 | WUN-H2-E02-060 | CEILING | A1 0.1 m | 1216Dfl0000046773/03 | m² | Trockenbauarbeiten | 3 | 0.1 | 0 | 1 | Bekleidung | A1 | 0 | 0 | NEW | Pset_CoveringCommon - AcousticRating: -
 | WUN-H2-E02-060 | CEILING | D1 0.001 m | 1216Dfl0000046773/04 | m² | Maler- und Lackierarbeiten | 4 | 0.001 | 0 | 1 | Bekleidung | D1 | 0 | 0 | NEW
Gipsfaserplatten 2-lagig (BSK) | WUN-H2-E02-060 | CEILING | layer 0.036 m | 1216Dfl0813003718/01 | m² | Trockenbauarbeiten | 1 | 0.036 | 0 | 1 | Deckenfläche |  | 0 | 0 | NEW | 2.5 | AllplanAttributes - Bezeichnung: Gipsfaserplatten 2-lagig (BSK); ash_lichte Raumhöhe: 2.5
 | WUN-H2-E02-060 | CEILING | Installationshöhe 0.714 m | 1216Dfl0813003718/02 | m² | Trockenbauarbeiten | 2 | 0.714 | 0 | 1 | Bekleidung | Installationshöhe | 0 | 0 | NEW | AllplanAttributes - OKFF: 0
 | WUN-H2-E02-060 | CEILING | Aa 0.15 m | 1216Dfl0813003718/03 | m² | Trockenbauarbeiten | 3 | 0.15 | 0 | 1 | Bekleidung | Aa | 0 | 0 | NEW | Pset_CoveringCommon - AcousticRating: -; AllplanAttributes - OKFF: 0
 | WUN-H2-E02-060 | CEILING | D1 0.001 m | 1216Dfl0813003718/04 | m² | Maler- und Lackierarbeiten | 4 | 0.001 | 0 | 1 | Bekleidung | D1 | 0 | 0 | NEW | AllplanAttributes - OKFF: 0
PVC Bahnenware Holzoptik | WUN-H2-E02-061 | FLOORING | Ku1 0.15 m | 1216Bfl0000046758/01 | m² | Bodenbelagsarbeiten | 1 | 0.15 | 0 | 1 | Bodenfläche | Ku1 | 0 | 0 | NEW | AllplanAttributes - Bezeichnung: PVC Bahnenware Holzoptik; Raumnr. Bauherr: 2.11_A2_02; ash B_Aufbau: B9; ash B_Rutschhemmung: R9
Gipsfaserplatten 2-lagig (BSK) | WUN-H2-E02-061 | CEILING | layer 0.036 m | 1216Dfl0813003266/01 | m² | Trockenbauarbeiten | 1 | 0.036 | 0 | 1 | Deckenfläche |  | 0 | 0 | NEW | 2.5 | AllplanAttributes - Bezeichnung: Gipsfaserplatten 2-lagig (BSK); ash_lichte Raumhöhe: 2.5
 | WUN-H2-E02-061 | CEILING | Installationshöhe 0.714 m | 1216Dfl0813003266/02 | m² | Trockenbauarbeiten | 2 | 0.714 | 0 | 1 | Bekleidung | Installationshöhe | 0 | 0 | NEW | AllplanAttributes - OKFF: 0
 | WUN-H2-E02-061 | CEILING | Aa 0.15 m | 1216Dfl0813003266/03 | m² | Trockenbauarbeiten | 3 | 0.15 | 0 | 1 | Bekleidung | Aa | 0 | 0 | NEW | Pset_CoveringCommon - AcousticRating: -; AllplanAttributes - OKFF: 0
 | WUN-H2-E02-061 | CEILING | D1 0.001 m | 1216Dfl0813003266/04 | m² | Maler- und Lackierarbeiten | 4 | 0.001 | 0 | 1 | Bekleidung | D1 | 0 | 0 | NEW | AllplanAttributes - OKFF: 0
Gipsfaserplatten 2-lagig (BSK) | WUN-H2-E02-061 | CEILING | layer 0.036 m | 1216Dfl0000046759/01 | m² | Trockenbauarbeiten | 1 | 0.036 | 0 | 1 | Deckenfläche |  | 0 | 0 | NEW | 3.15 | AllplanAttributes - Bezeichnung: Gipsfaserplatten 2-lagig (BSK); ash_lichte Raumhöhe: 3.1
 | WUN-H2-E02-061 | CEILING | Installationshöhe 0.164 m | 1216Dfl0000046759/02 | m² | Trockenbauarbeiten | 2 | 0.164 | 0 | 1 | Bekleidung | Installationshöhe | 0 | 0 | NEW | Pset_CoveringCommon - AcousticRating: -
 | WUN-H2-E02-061 | CEILING | A1 0.1 m | 1216Dfl0000046759/03 | m² | Trockenbauarbeiten | 3 | 0.1 | 0 | 1 | Bekleidung | A1 | 0 | 0 | NEW | Pset_CoveringCommon - AcousticRating: -
 | WUN-H2-E02-061 | CEILING | D1 0.001 m | 1216Dfl0000046759/04 | m² | Maler- und Lackierarbeiten | 4 | 0.001 | 0 | 1 | Bekleidung | D1 | 0 | 0 | NEW
Gipsfaserplatten 2-lagig (BSK) | WUN-H2-E02-061 | CEILING | layer 0.036 m | 1216Dfl0000046770/01 | m² | Trockenbauarbeiten | 1 | 0.036 | 0 | 1 | Deckenfläche |  | 0 | 0 | NEW | 2.5 | AllplanAttributes - Bezeichnung: Gipsfaserplatten 2-lagig (BSK); ash_lichte Raumhöhe: 2.5
 | WUN-H2-E02-061 | CEILING | Installationshöhe 0.714 m | 1216Dfl0000046770/02 | m² | Trockenbauarbeiten | 2 | 0.714 | 0 | 1 | Bekleidung | Installationshöhe | 0 | 0 | NEW | AllplanAttributes - OKFF: 0
 | WUN-H2-E02-061 | CEILING | A1 0.15 m | 1216Dfl0000046770/03 | m² | Trockenbauarbeiten | 3 | 0.15 | 0 | 1 | Bekleidung | A1 | 0 | 0 | NEW | Pset_CoveringCommon - AcousticRating: -; AllplanAttributes - OKFF: 0
 | WUN-H2-E02-061 | CEILING | D1 0.001 m | 1216Dfl0000046770/04 | m² | Maler- und Lackierarbeiten | 4 | 0.001 | 0 | 1 | Bekleidung | D1 | 0 | 0 | NEW | AllplanAttributes - OKFF: 0
PVC Bahnenware Holzoptik | WUN-H2-E02-003 | FLOORING | Ku1 0.15 m | 1216Bfl0000046694/01 | m² | Bodenbelagsarbeiten | 1 | 0.15 | 0 | 1 | Bodenfläche | Ku1 | 0 | 0 | NEW | AllplanAttributes - Bezeichnung: PVC Bahnenware Holzoptik; Raumnr. Bauherr: 2.11_A2_02; ash B_Aufbau: B9; ash B_Rutschhemmung: R9
Gipsfaserplatten 2-lagig (BSK) | WUN-H2-E02-003 | CEILING | layer 0.036 m | 1216Dfl0813004180/01 | m² | Trockenbauarbeiten | 1 | 0.036 | 0 | 1 | Deckenfläche |  | 0 | 0 | NEW | 2.5 | AllplanAttributes - Bezeichnung: Gipsfaserplatten 2-lagig (BSK); ash_lichte Raumhöhe: 2.5
 | WUN-H2-E02-003 | CEILING | Installationshöhe 0.714 m | 1216Dfl0813004180/02 | m² | Trockenbauarbeiten | 2 | 0.714 | 0 | 1 | Bekleidung | Installationshöhe | 0 | 0 | NEW | AllplanAttributes - OKFF: 0
 | WUN-H2-E02-003 | CEILING | Aa 0.15 m | 1216Dfl0813004180/03 | m² | Trockenbauarbeiten | 3 | 0.15 | 0 | 1 | Bekleidung | Aa | 0 | 0 | NEW | Pset_CoveringCommon - AcousticRating: -; AllplanAttributes - OKFF: 0
 | WUN-H2-E02-003 | CEILING | D1 0.001 m | 1216Dfl0813004180/04 | m² | Maler- und Lackierarbeiten | 4 | 0.001 | 0 | 1 | Bekleidung | D1 | 0 | 0 | NEW | AllplanAttributes - OKFF: 0
Gipsfaserplatten 2-lagig (BSK) | WUN-H2-E02-003 | CEILING | layer 0.036 m | 1216Dfl0000046706/01 | m² | Trockenbauarbeiten | 1 | 0.036 | 0 | 1 | Deckenfläche |  | 0 | 0 | NEW | 2.5 | AllplanAttributes - Bezeichnung: Gipsfaserplatten 2-lagig (BSK); ash_lichte Raumhöhe: 2.5
 | WUN-H2-E02-003 | CEILING | Installationshöhe 0.714 m | 1216Dfl0000046706/02 | m² | Trockenbauarbeiten | 2 | 0.714 | 0 | 1 | Bekleidung | Installationshöhe | 0 | 0 | NEW | AllplanAttributes - OKFF: 0
 | WUN-H2-E02-003 | CEILING | A1 0.15 m | 1216Dfl0000046706/03 | m² | Trockenbauarbeiten | 3 | 0.15 | 0 | 1 | Bekleidung | A1 | 0 | 0 | NEW | Pset_CoveringCommon - AcousticRating: -; AllplanAttributes - OKFF: 0
 | WUN-H2-E02-003 | CEILING | D1 0.001 m | 1216Dfl0000046706/04 | m² | Maler- und Lackierarbeiten | 4 | 0.001 | 0 | 1 | Bekleidung | D1 | 0 | 0 | NEW | AllplanAttributes - OKFF: 0
Gipsfaserplatten 2-lagig (BSK) | WUN-H2-E02-003 | CEILING | layer 0.036 m | 1216Dfl0000046695/01 | m² | Trockenbauarbeiten | 1 | 0.036 | 0 | 1 | Deckenfläche |  | 0 | 0 | NEW | 3.15 | AllplanAttributes - Bezeichnung: Gipsfaserplatten 2-lagig (BSK); ash_lichte Raumhöhe: 3.1
 | WUN-H2-E02-003 | CEILING | Installationshöhe 0.164 m | 1216Dfl0000046695/02 | m² | Trockenbauarbeiten | 2 | 0.164 | 0 | 1 | Bekleidung | Installationshöhe | 0 | 0 | NEW | Pset_CoveringCommon - AcousticRating: -
 | WUN-H2-E02-003 | CEILING | A1 0.1 m | 1216Dfl0000046695/03 | m² | Trockenbauarbeiten | 3 | 0.1 | 0 | 1 | Bekleidung | A1 | 0 | 0 | NEW | Pset_CoveringCommon - AcousticRating: -
 | WUN-H2-E02-003 | CEILING | D1 0.001 m | 1216Dfl0000046695/04 | m² | Maler- und Lackierarbeiten | 4 | 0.001 | 0 | 1 | Bekleidung | D1 | 0 | 0 | NEW
PVC Bahnenware Holzoptik | WUN-H2-E02-041 | FLOORING | Ku1 0.15 m | 1216Bfl0812778609/01 | m² | Bodenbelagsarbeiten | 1 | 0.15 | 0 | 1 | Bodenfläche | Ku1 | 0 | 0 | NEW | AllplanAttributes - Bezeichnung: PVC Bahnenware Holzoptik; Raumnr. Bauherr: 2.11_A2_02; ash B_Aufbau: B9; ash B_Rutschhemmung: R9
Acrovyn | WUN-H2-E02-041 | CLADDING | 84 0.001 m | 1216Sfl0812841526/02 | m² | Maler- und Lackierarbeiten | 2 | 0.001 | 0 | 1 | Seitenfläche | 84 | 0 | 0 | NEW | AllplanAttributes - Bezeichnung: Acrovyn
Acrovyn | WUN-H2-E02-041 | CLADDING | 84 0.001 m | 1216Sfl0812841235/02 | m² | Maler- und Lackierarbeiten | 2 | 0.001 | 0 | 1 | Seitenfläche | 84 | 0 | 0 | NEW | AllplanAttributes - Bezeichnung: Acrovyn
Gipsfaserplatten 2-lagig (BSK) | WUN-H2-E02-041 | CEILING | layer 0.036 m | 1216Dfl0812778610/01 | m² | Trockenbauarbeiten | 1 | 0.036 | 0 | 1 | Deckenfläche |  | 0 | 0 | NEW | 3.15 | AllplanAttributes - Bezeichnung: Gipsfaserplatten 2-lagig (BSK); ash_lichte Raumhöhe: 3.47389
 | WUN-H2-E02-041 | CEILING | A1 0.1 m | 1216Dfl0812778583/01 | m² | Trockenbauarbeiten | 1 | 0.1 | 0 | 1 | Bekleidung | A1 | 0 | 0 | NEW | 2.5 | AllplanAttributes - ash_lichte Raumhöhe: 2.5; OKFF: 0; Pset_CoveringCommon - AcousticRating: -
 | WUN-H2-E02-041 | CEILING | D1 0.001 m | 1216Dfl0812778583/02 | m² | Maler- und Lackierarbeiten | 2 | 0.001 | 0 | 1 | Bekleidung | D1 | 0 | 0 | NEW | AllplanAttributes - OKFF: 0
 | WUN-H2-E02-041 | CEILING | A1 0.1 m | 1216Dfl0813302564/01 | m² | Trockenbauarbeiten | 1 | 0.1 | 0 | 1 | Bekleidung | A1 | 0 | 0 | NEW | 2.5 | AllplanAttributes - ash_lichte Raumhöhe: 3.150000; OKFF: 0; Pset_CoveringCommon - AcousticRating: -
 | WUN-H2-E02-041 | CEILING | D1 0.001 m | 1216Dfl0813302564/02 | m² | Maler- und Lackierarbeiten | 2 | 0.001 | 0 | 1 | Bekleidung | D1 | 0 | 0 | NEW | 2.5 | AllplanAttributes - ash_lichte Raumhöhe: 3.150000; OKFF: 0
PVC Bahnenware Uni | WUN-H2-E02-038 | FLOORING | Ku2 0.15 m | 1216Bfl0000046050/01 | m² | Bodenbelagsarbeiten | 1 | 0.15 | 0 | 1 | Bodenfläche | Ku2 | 0 | 0 | NEW | AllplanAttributes - Bezeichnung: PVC Bahnenware Uni; Raumnr. Bauherr: 2.11_A2_02; ash B_Aufbau: B9; ash B_Rutschhemmung: R9
Gipsfaserplatten 2-lagig (BSK) | WUN-H2-E02-038 | CEILING | layer 0.036 m | 1216Dfl0000046051/01 | m² | Trockenbauarbeiten | 1 | 0.036 | 0 | 1 | Deckenfläche |  | 0 | 0 | NEW | 3.15 | AllplanAttributes - Bezeichnung: Gipsfaserplatten 2-lagig (BSK); ash_lichte Raumhöhe: 3.87291
Rasterdecke | WUN-H2-E02-038 | CEILING | E3 0.1 m | 1216Dfl0813303323/01 | m² | Trockenbauarbeiten | 1 | 0.1 | 0 | 1 | Bekleidung | E3 | 0 | 0 | NEW | 2.5 | AllplanAttributes - Bezeichnung: Rasterdecke; ash_lichte Raumhöhe: 2.5; Pset_CoveringCommon - AcousticRating: -
Fliesen | WUN-H2-E02-030 | FLOORING | Fl1 0.15 m | 1216Bfl0000046142/01 | m² | Bodenbelagsarbeiten | 1 | 0.15 | 0 | 1 | Bodenfläche | Fl1 | 0 | 0 | NEW | AllplanAttributes - Bezeichnung: Fliesen; Raumnr. Bauherr: 2.11_A2_02; ash B_Aufbau: B10; ash B_Rutschhemmung: R10
Gipsfaserplatten 2-lagig (BSK) | WUN-H2-E02-030 | CEILING | layer 0.036 m | 1216Dfl0000046143/01 | m² | Trockenbauarbeiten | 1 | 0.036 | 0 | 1 | Deckenfläche |  | 0 | 0 | NEW | 3.15 | AllplanAttributes - Bezeichnung: Gipsfaserplatten 2-lagig (BSK); ash_lichte Raumhöhe: 3.76083
Rasterdecke | WUN-H2-E02-030 | CEILING | E3 0.1 m | 1216Dfl0813303714/01 | m² | Trockenbauarbeiten | 1 | 0.1 | 0 | 1 | Bekleidung | E3 | 0 | 0 | NEW | 2.5 | AllplanAttributes - Bezeichnung: Rasterdecke; ash_lichte Raumhöhe: 2.5; Pset_CoveringCommon - AcousticRating: -
Fliesen | WUN-H2-E02-031 | FLOORING | Fl1 0.15 m | 1216Bfl0000046130/01 | m² | Bodenbelagsarbeiten | 1 | 0.15 | 0 | 1 | Bodenfläche | Fl1 | 0 | 0 | NEW | AllplanAttributes - Bezeichnung: Fliesen; Raumnr. Bauherr: 2.11_A2_02; ash B_Aufbau: B10; ash B_Rutschhemmung: R10
Gipsfaserplatten 2-lagig (BSK) | WUN-H2-E02-031 | CEILING | layer 0.036 m | 1216Dfl0000046131/01 | m² | Trockenbauarbeiten | 1 | 0.036 | 0 | 1 | Deckenfläche |  | 0 | 0 | NEW | 3.15 | AllplanAttributes - Bezeichnung: Gipsfaserplatten 2-lagig (BSK); ash_lichte Raumhöhe: 3.76083
Rasterdecke | WUN-H2-E02-031 | CEILING | E3 0.1 m | 1216Dfl0813303606/01 | m² | Trockenbauarbeiten | 1 | 0.1 | 0 | 1 | Bekleidung | E3 | 0 | 0 | NEW | 2.5 | AllplanAttributes - Bezeichnung: Rasterdecke; ash_lichte Raumhöhe: 2.5; Pset_CoveringCommon - AcousticRating: -
PVC Bahnenware Uni | WUN-H2-E02-026 | FLOORING | Ku2 0.15 m | 1216Bfl0000046166/01 | m² | Bodenbelagsarbeiten | 1 | 0.15 | 0 | 1 | Bodenfläche | Ku2 | 0 | 0 | NEW | AllplanAttributes - Bezeichnung: PVC Bahnenware Uni; Raumnr. Bauherr: 2.11_A2_02; ash B_Aufbau: B9; ash B_Rutschhemmung: R9
Gipsfaserplatten 2-lagig (BSK) | WUN-H2-E02-026 | CEILING | layer 0.036 m | 1216Dfl0000046167/01 | m² | Trockenbauarbeiten | 1 | 0.036 | 0 | 1 | Deckenfläche |  | 0 | 0 | NEW | 3.15 | AllplanAttributes - Bezeichnung: Gipsfaserplatten 2-lagig (BSK); ash_lichte Raumhöhe: 3.42589
Rasterdecke | WUN-H2-E02-026 | CEILING | E3 0.1 m | 1216Dfl0813303317/01 | m² | Trockenbauarbeiten | 1 | 0.1 | 0 | 1 | Bekleidung | E3 | 0 | 0 | NEW | 2.5 | AllplanAttributes - Bezeichnung: Rasterdecke; ash_lichte Raumhöhe: 2.5; Pset_CoveringCommon - AcousticRating: -
PVC Bahnenware Uni | WUN-H2-E02-040 | FLOORING | Ku2 0.15 m | 1216Bfl0000046026/01 | m² | Bodenbelagsarbeiten | 1 | 0.15 | 0 | 1 | Bodenfläche | Ku2 | 0 | 0 | NEW | AllplanAttributes - Bezeichnung: PVC Bahnenware Uni; Raumnr. Bauherr: 2.11_A2_02; ash B_Aufbau: B9; ash B_Rutschhemmung: R9
Gipsfaserplatten 2-lagig (BSK) | WUN-H2-E02-040 | CEILING | layer 0.036 m | 1216Dfl0000046027/01 | m² | Trockenbauarbeiten | 1 | 0.036 | 0 | 1 | Deckenfläche |  | 0 | 0 | NEW | 3.15 | AllplanAttributes - Bezeichnung: Gipsfaserplatten 2-lagig (BSK); ash_lichte Raumhöhe: 3.4387
Rasterdecke | WUN-H2-E02-040 | CEILING | E3 0.1 m | 1216Dfl0813303326/01 | m² | Trockenbauarbeiten | 1 | 0.1 | 0 | 1 | Bekleidung | E3 | 0 | 0 | NEW | 2.5 | AllplanAttributes - Bezeichnung: Rasterdecke; ash_lichte Raumhöhe: 2.5; Pset_CoveringCommon - AcousticRating: -
PVC | WUN-H2-E02-029 | FLOORING | Ku3 0.15 m | 1216Bfl0000046154/01 | m² | Bodenbelagsarbeiten | 1 | 0.15 | 0 | 1 | Bodenfläche | Ku3 | 0 | 0 | NEW | AllplanAttributes - Bezeichnung: PVC; Raumnr. Bauherr: 2.11_A2_02; ash B_Aufbau: B9; ash B_Rutschhemmung: R9
Gipsfaserplatten 2-lagig (BSK) | WUN-H2-E02-029 | CEILING | layer 0.036 m | 1216Dfl0000046155/01 | m² | Trockenbauarbeiten | 1 | 0.036 | 0 | 1 | Deckenfläche |  | 0 | 0 | NEW | 3.15 | AllplanAttributes - Bezeichnung: Gipsfaserplatten 2-lagig (BSK); ash_lichte Raumhöhe: 3.74529
PVC Bahnenware Uni | WUN-H2-E02-032 | FLOORING | Ku2 0.15 m | 1216Bfl0000046063/01 | m² | Bodenbelagsarbeiten | 1 | 0.15 | 0 | 1 | Bodenfläche | Ku2 | 0 | 0 | NEW | AllplanAttributes - Bezeichnung: PVC Bahnenware Uni; Raumnr. Bauherr: 2.11_A2_02; ash B_Aufbau: B9; ash B_Rutschhemmung: R9
Gipsfaserplatten 2-lagig (BSK) | WUN-H2-E02-032 | CEILING | layer 0.036 m | 1216Dfl0000046062/01 | m² | Trockenbauarbeiten | 1 | 0.036 | 0 | 1 | Deckenfläche |  | 0 | 0 | NEW | 3.15 | AllplanAttributes - Bezeichnung: Gipsfaserplatten 2-lagig (BSK); ash_lichte Raumhöhe: 3.87662
Rasterdecke | WUN-H2-E02-032 | CEILING | E3 0.1 m | 1216Dfl0813303320/01 | m² | Trockenbauarbeiten | 1 | 0.1 | 0 | 1 | Bekleidung | E3 | 0 | 0 | NEW | 2.5 | AllplanAttributes - Bezeichnung: Rasterdecke; ash_lichte Raumhöhe: 2.5; Pset_CoveringCommon - AcousticRating: -
Fliesen | WUN-H2-E02-039 | FLOORING | Fl1 0.15 m | 1216Bfl0000046039/01 | m² | Bodenbelagsarbeiten | 1 | 0.15 | 0 | 1 | Bodenfläche | Fl1 | 0 | 0 | NEW | AllplanAttributes - Bezeichnung: Fliesen; Raumnr. Bauherr: 2.11_A2_02; ash B_Aufbau: B10; ash B_Rutschhemmung: R10
Fliesen Mosaik | WUN-H2-E02-039 | FLOORING | Fl2 0.15 m | 1216Bfl0813115664/01 | m² | Bodenbelagsarbeiten | 1 | 0.15 | 0 | 1 | Bodenfläche | Fl2 | 0 | 0 | NEW | AllplanAttributes - Bezeichnung: Fliesen Mosaik; Raumnr. Bauherr: 2.11_A2_02; ash B_Aufbau: B11; ash B_Rutschhemmung: R10; ash B_Bewertungsgruppe Barfußbereich: B
Gipsfaserplatten 2-lagig (BSK) | WUN-H2-E02-039 | CEILING | layer 0.036 m | 1216Dfl0000046038/01 | m² | Trockenbauarbeiten | 1 | 0.036 | 0 | 1 | Deckenfläche |  | 0 | 0 | NEW | 3.15 | AllplanAttributes - Bezeichnung: Gipsfaserplatten 2-lagig (BSK); ash_lichte Raumhöhe: 3.66064
 | WUN-H2-E02-039 | CEILING | B 0.1 m | 1216Dfl0813303329/01 | m² | Trockenbauarbeiten | 1 | 0.1 | 0 | 1 | Bekleidung | B | 0 | 0 | NEW | 2.5 | AllplanAttributes - ash_lichte Raumhöhe: 2.5; OKFF: 0; Pset_CoveringCommon - AcousticRating: -
 | WUN-H2-E02-039 | CEILING | D1 0.001 m | 1216Dfl0813303329/02 | m² | Maler- und Lackierarbeiten | 2 | 0.001 | 0 | 1 | Bekleidung | D1 | 0 | 0 | NEW | AllplanAttributes - OKFF: 0
PVC Bahnenware Holzoptik | WUN-H2-E02-035 | FLOORING | Ku1 0.15 m | 1216Bfl0000047610/01 | m² | Bodenbelagsarbeiten | 1 | 0.15 | 0 | 1 | Bodenfläche | Ku1 | 0 | 0 | NEW | AllplanAttributes - Bezeichnung: PVC Bahnenware Holzoptik; Raumnr. Bauherr: 2.11_A2_02; ash B_Aufbau: B9; ash B_Rutschhemmung: R9
Gipsfaserplatten 2-lagig (BSK) | WUN-H2-E02-035 | CEILING | layer 0.036 m | 1216Dfl0813275869/01 | m² | Trockenbauarbeiten | 1 | 0.036 | 0 | 1 | Deckenfläche |  | 0 | 0 | NEW | 3.15 | AllplanAttributes - Bezeichnung: Gipsfaserplatten 2-lagig (BSK); ash_lichte Raumhöhe: 4.41295
 | WUN-H2-E02-035 | CEILING | A1 0.1 m | 1216Dfl0000047622/01 | m² | Trockenbauarbeiten | 1 | 0.1 | 0 | 1 | Bekleidung | A1 | 0 | 0 | NEW | 2.5 | AllplanAttributes - ash_lichte Raumhöhe: 2.5; OKFF: 0; Pset_CoveringCommon - AcousticRating: -
 | WUN-H2-E02-035 | CEILING | D1 0.001 m | 1216Dfl0000047622/02 | m² | Maler- und Lackierarbeiten | 2 | 0.001 | 0 | 1 | Bekleidung | D1 | 0 | 0 | NEW | AllplanAttributes - OKFF: 0
 | WUN-H2-E02-035 | CEILING | Aa 0.1 m | 1216Dfl0812842795/01 | m² | Trockenbauarbeiten | 1 | 0.1 | 0 | 1 | Bekleidung | Aa | 0 | 0 | NEW | 2.5 | AllplanAttributes - ash_lichte Raumhöhe: 2.5; OKFF: 0; Pset_CoveringCommon - AcousticRating: -
 | WUN-H2-E02-035 | CEILING | D1 0.001 m | 1216Dfl0812842795/02 | m² | Maler- und Lackierarbeiten | 2 | 0.001 | 0 | 1 | Bekleidung | D1 | 0 | 0 | NEW | AllplanAttributes - OKFF: 0
PVC Bahnenware Holzoptik | WUN-H2-E02-034 | FLOORING | Ku1 0.15 m | 1216Bfl0000046088/01 | m² | Bodenbelagsarbeiten | 1 | 0.15 | 0 | 1 | Bodenfläche | Ku1 | 0 | 0 | NEW | AllplanAttributes - Bezeichnung: PVC Bahnenware Holzoptik; Raumnr. Bauherr: 2.11_A2_02; ash B_Aufbau: B9; ash B_Rutschhemmung: R9
Gipsfaserplatten 2-lagig (BSK) | WUN-H2-E02-034 | CEILING | layer 0.036 m | 1216Dfl0813275868/01 | m² | Trockenbauarbeiten | 1 | 0.036 | 0 | 1 | Deckenfläche |  | 0 | 0 | NEW | 3.15 | AllplanAttributes - Bezeichnung: Gipsfaserplatten 2-lagig (BSK); ash_lichte Raumhöhe: 4.40747
 | WUN-H2-E02-034 | CEILING | A1 0.1 m | 1216Dfl0000046100/01 | m² | Trockenbauarbeiten | 1 | 0.1 | 0 | 1 | Bekleidung | A1 | 0 | 0 | NEW | 2.5 | AllplanAttributes - ash_lichte Raumhöhe: 2.5; OKFF: 0; Pset_CoveringCommon - AcousticRating: -
 | WUN-H2-E02-034 | CEILING | D1 0.001 m | 1216Dfl0000046100/02 | m² | Maler- und Lackierarbeiten | 2 | 0.001 | 0 | 1 | Bekleidung | D1 | 0 | 0 | NEW | AllplanAttributes - OKFF: 0
 | WUN-H2-E02-034 | CEILING | Aa 0.1 m | 1216Dfl0812860380/01 | m² | Trockenbauarbeiten | 1 | 0.1 | 0 | 1 | Bekleidung | Aa | 0 | 0 | NEW | 2.5 | AllplanAttributes - ash_lichte Raumhöhe: 2.5; OKFF: 0; Pset_CoveringCommon - AcousticRating: -
 | WUN-H2-E02-034 | CEILING | D1 0.001 m | 1216Dfl0812860380/02 | m² | Maler- und Lackierarbeiten | 2 | 0.001 | 0 | 1 | Bekleidung | D1 | 0 | 0 | NEW | AllplanAttributes - OKFF: 0
PVC Bahnenware Holzoptik | WUN-H2-E02-036 | FLOORING | Ku1 0.15 m | 1216Bfl0000046102/01 | m² | Bodenbelagsarbeiten | 1 | 0.15 | 0 | 1 | Bodenfläche | Ku1 | 0 | 0 | NEW | AllplanAttributes - Bezeichnung: PVC Bahnenware Holzoptik; Raumnr. Bauherr: 2.11_A2_02; ash B_Aufbau: B9; ash B_Rutschhemmung: R9
Gipsfaserplatten 2-lagig (BSK) | WUN-H2-E02-036 | CEILING | layer 0.036 m | 1216Dfl0813275867/01 | m² | Trockenbauarbeiten | 1 | 0.036 | 0 | 1 | Deckenfläche |  | 0 | 0 | NEW | 3.15 | AllplanAttributes - Bezeichnung: Gipsfaserplatten 2-lagig (BSK); ash_lichte Raumhöhe: 4.40747
 | WUN-H2-E02-036 | CEILING | Aa 0.1 m | 1216Dfl0812843380/01 | m² | Trockenbauarbeiten | 1 | 0.1 | 0 | 1 | Bekleidung | Aa | 0 | 0 | NEW | 2.5 | AllplanAttributes - ash_lichte Raumhöhe: 2.5; OKFF: 0; Pset_CoveringCommon - AcousticRating: -
 | WUN-H2-E02-036 | CEILING | D1 0.001 m | 1216Dfl0812843380/02 | m² | Maler- und Lackierarbeiten | 2 | 0.001 | 0 | 1 | Bekleidung | D1 | 0 | 0 | NEW | AllplanAttributes - OKFF: 0
 | WUN-H2-E02-036 | CEILING | A1 0.1 m | 1216Dfl0000046114/01 | m² | Trockenbauarbeiten | 1 | 0.1 | 0 | 1 | Bekleidung | A1 | 0 | 0 | NEW | 2.5 | AllplanAttributes - ash_lichte Raumhöhe: 2.5; OKFF: 0; Pset_CoveringCommon - AcousticRating: -
 | WUN-H2-E02-036 | CEILING | D1 0.001 m | 1216Dfl0000046114/02 | m² | Maler- und Lackierarbeiten | 2 | 0.001 | 0 | 1 | Bekleidung | D1 | 0 | 0 | NEW | AllplanAttributes - OKFF: 0
PVC Bahnenware Holzoptik | WUN-H2-E02-033 | FLOORING | Ku1 0.15 m | 1216Bfl0000046074/01 | m² | Bodenbelagsarbeiten | 1 | 0.15 | 0 | 1 | Bodenfläche | Ku1 | 0 | 0 | NEW | AllplanAttributes - Bezeichnung: PVC Bahnenware Holzoptik; Raumnr. Bauherr: 2.11_A2_02; ash B_Aufbau: B9; ash B_Rutschhemmung: R9
Gipsfaserplatten 2-lagig (BSK) | WUN-H2-E02-033 | CEILING | layer 0.036 m | 1216Dfl0813275866/01 | m² | Trockenbauarbeiten | 1 | 0.036 | 0 | 1 | Deckenfläche |  | 0 | 0 | NEW | 3.15 | AllplanAttributes - Bezeichnung: Gipsfaserplatten 2-lagig (BSK); ash_lichte Raumhöhe: 4.40747
 | WUN-H2-E02-033 | CEILING | A1 0.1 m | 1216Dfl0000046086/01 | m² | Trockenbauarbeiten | 1 | 0.1 | 0 | 1 | Bekleidung | A1 | 0 | 0 | NEW | 2.5 | AllplanAttributes - ash_lichte Raumhöhe: 2.5; OKFF: 0; Pset_CoveringCommon - AcousticRating: -
 | WUN-H2-E02-033 | CEILING | D1 0.001 m | 1216Dfl0000046086/02 | m² | Maler- und Lackierarbeiten | 2 | 0.001 | 0 | 1 | Bekleidung | D1 | 0 | 0 | NEW | AllplanAttributes - OKFF: 0
 | WUN-H2-E02-033 | CEILING | Aa 0.1 m | 1216Dfl0812861539/01 | m² | Trockenbauarbeiten | 1 | 0.1 | 0 | 1 | Bekleidung | Aa | 0 | 0 | NEW | 2.5 | AllplanAttributes - ash_lichte Raumhöhe: 2.5; OKFF: 0; Pset_CoveringCommon - AcousticRating: -
 | WUN-H2-E02-033 | CEILING | D1 0.001 m | 1216Dfl0812861539/02 | m² | Maler- und Lackierarbeiten | 2 | 0.001 | 0 | 1 | Bekleidung | D1 | 0 | 0 | NEW | AllplanAttributes - OKFF: 0
PVC Bahnenware Holzoptik | WUN-H2-E02-037 | FLOORING | Ku1 0.15 m | 1216Bfl0000046116/01 | m² | Bodenbelagsarbeiten | 1 | 0.15 | 0 | 1 | Bodenfläche | Ku1 | 0 | 0 | NEW | AllplanAttributes - Bezeichnung: PVC Bahnenware Holzoptik; Raumnr. Bauherr: 2.11_A2_02; ash B_Aufbau: B9; ash B_Rutschhemmung: R9
Gipsfaserplatten 2-lagig (BSK) | WUN-H2-E02-037 | CEILING | layer 0.036 m | 1216Dfl0813275865/01 | m² | Trockenbauarbeiten | 1 | 0.036 | 0 | 1 | Deckenfläche |  | 0 | 0 | NEW | 3.15 | AllplanAttributes - Bezeichnung: Gipsfaserplatten 2-lagig (BSK); ash_lichte Raumhöhe: 4.40205
 | WUN-H2-E02-037 | CEILING | Aa 0.1 m | 1216Dfl0812843965/01 | m² | Trockenbauarbeiten | 1 | 0.1 | 0 | 1 | Bekleidung | Aa | 0 | 0 | NEW | 2.5 | AllplanAttributes - ash_lichte Raumhöhe: 2.5; OKFF: 0; Pset_CoveringCommon - AcousticRating: -
 | WUN-H2-E02-037 | CEILING | D1 0.001 m | 1216Dfl0812843965/02 | m² | Maler- und Lackierarbeiten | 2 | 0.001 | 0 | 1 | Bekleidung | D1 | 0 | 0 | NEW | AllplanAttributes - OKFF: 0
 | WUN-H2-E02-037 | CEILING | A1 0.1 m | 1216Dfl0000046128/01 | m² | Trockenbauarbeiten | 1 | 0.1 | 0 | 1 | Bekleidung | A1 | 0 | 0 | NEW | 2.5 | AllplanAttributes - ash_lichte Raumhöhe: 2.5; OKFF: 0; Pset_CoveringCommon - AcousticRating: -
 | WUN-H2-E02-037 | CEILING | D1 0.001 m | 1216Dfl0000046128/02 | m² | Maler- und Lackierarbeiten | 2 | 0.001 | 0 | 1 | Bekleidung | D1 | 0 | 0 | NEW | AllplanAttributes - OKFF: 0
PVC Bahnenware Holzoptik | WUN-H2-E02-043 | FLOORING | Ku1 0.15 m | 1216Bfl0000045896/01 | m² | Bodenbelagsarbeiten | 1 | 0.15 | 0 | 1 | Bodenfläche | Ku1 | 0 | 0 | NEW | AllplanAttributes - Bezeichnung: PVC Bahnenware Holzoptik; Raumnr. Bauherr: 2.11_A2_02; ash B_Aufbau: B9; ash B_Rutschhemmung: R9
Acrovyn | WUN-H2-E02-043 | CLADDING | 84 0.001 m | 1216Sfl0812842399/02 | m² | Maler- und Lackierarbeiten | 2 | 0.001 | 0 | 1 | Seitenfläche | 84 | 0 | 0 | NEW | AllplanAttributes - Bezeichnung: Acrovyn
Acrovyn | WUN-H2-E02-043 | CLADDING | 84 0.001 m | 1216Sfl0812842724/02 | m² | Maler- und Lackierarbeiten | 2 | 0.001 | 0 | 1 | Seitenfläche | 84 | 0 | 0 | NEW | AllplanAttributes - Bezeichnung: Acrovyn
Gipsfaserplatten 2-lagig (BSK) | WUN-H2-E02-043 | CEILING | layer 0.036 m | 1216Dfl0000045897/01 | m² | Trockenbauarbeiten | 1 | 0.036 | 0 | 1 | Deckenfläche |  | 0 | 0 | NEW | 3.15 | AllplanAttributes - Bezeichnung: Gipsfaserplatten 2-lagig (BSK); ash_lichte Raumhöhe: 4.3691
 | WUN-H2-E02-043 | CEILING | A1 0.1 m | 1216Dfl0000045908/01 | m² | Trockenbauarbeiten | 1 | 0.1 | 0 | 1 | Bekleidung | A1 | 0 | 0 | NEW | 2.5 | AllplanAttributes - ash_lichte Raumhöhe: 2.5; OKFF: 0; Pset_CoveringCommon - AcousticRating: -
 | WUN-H2-E02-043 | CEILING | D1 0.001 m | 1216Dfl0000045908/02 | m² | Maler- und Lackierarbeiten | 2 | 0.001 | 0 | 1 | Bekleidung | D1 | 0 | 0 | NEW | AllplanAttributes - OKFF: 0
 | WUN-H2-E02-043 | CEILING | A1 0.1 m | 1216Dfl0813302572/01 | m² | Trockenbauarbeiten | 1 | 0.1 | 0 | 1 | Bekleidung | A1 | 0 | 0 | NEW | 2.5 | AllplanAttributes - ash_lichte Raumhöhe: 3.150000; OKFF: 0; Pset_CoveringCommon - AcousticRating: -
 | WUN-H2-E02-043 | CEILING | D1 0.001 m | 1216Dfl0813302572/02 | m² | Maler- und Lackierarbeiten | 2 | 0.001 | 0 | 1 | Bekleidung | D1 | 0 | 0 | NEW | 2.5 | AllplanAttributes - ash_lichte Raumhöhe: 3.150000; OKFF: 0
PVC Bahnenware Holzoptik | WUN-H2-E02-042 | FLOORING | Ku1 0.15 m | 1216Bfl0000045882/01 | m² | Bodenbelagsarbeiten | 1 | 0.15 | 0 | 1 | Bodenfläche | Ku1 | 0 | 0 | NEW | AllplanAttributes - Bezeichnung: PVC Bahnenware Holzoptik; Raumnr. Bauherr: 2.11_A2_02; ash B_Aufbau: B9; ash B_Rutschhemmung: R9
Acrovyn | WUN-H2-E02-042 | CLADDING | 84 0.001 m | 1216Sfl0812841817/02 | m² | Maler- und Lackierarbeiten | 2 | 0.001 | 0 | 1 | Seitenfläche | 84 | 0 | 0 | NEW | AllplanAttributes - Bezeichnung: Acrovyn
Acrovyn | WUN-H2-E02-042 | CLADDING | 84 0.001 m | 1216Sfl0812842108/02 | m² | Maler- und Lackierarbeiten | 2 | 0.001 | 0 | 1 | Seitenfläche | 84 | 0 | 0 | NEW | AllplanAttributes - Bezeichnung: Acrovyn
Gipsfaserplatten 2-lagig (BSK) | WUN-H2-E02-042 | CEILING | layer 0.036 m | 1216Dfl0812777496/01 | m² | Trockenbauarbeiten | 1 | 0.036 | 0 | 1 | Deckenfläche |  | 0 | 0 | NEW | 3.15 | AllplanAttributes - Bezeichnung: Gipsfaserplatten 2-lagig (BSK); ash_lichte Raumhöhe: 3.95762
 | WUN-H2-E02-042 | CEILING | A1 0.1 m | 1216Dfl0000045894/01 | m² | Trockenbauarbeiten | 1 | 0.1 | 0 | 1 | Bekleidung | A1 | 0 | 0 | NEW | 2.5 | AllplanAttributes - ash_lichte Raumhöhe: 2.5; OKFF: 0; Pset_CoveringCommon - AcousticRating: -
 | WUN-H2-E02-042 | CEILING | D1 0.001 m | 1216Dfl0000045894/02 | m² | Maler- und Lackierarbeiten | 2 | 0.001 | 0 | 1 | Bekleidung | D1 | 0 | 0 | NEW | AllplanAttributes - OKFF: 0
 | WUN-H2-E02-042 | CEILING | A1 0.1 m | 1216Dfl0813302568/01 | m² | Trockenbauarbeiten | 1 | 0.1 | 0 | 1 | Bekleidung | A1 | 0 | 0 | NEW | 2.5 | AllplanAttributes - ash_lichte Raumhöhe: 3.150000; OKFF: 0; Pset_CoveringCommon - AcousticRating: -
 | WUN-H2-E02-042 | CEILING | D1 0.001 m | 1216Dfl0813302568/02 | m² | Maler- und Lackierarbeiten | 2 | 0.001 | 0 | 1 | Bekleidung | D1 | 0 | 0 | NEW | 2.5 | AllplanAttributes - ash_lichte Raumhöhe: 3.150000; OKFF: 0
PVC Bahnenware Holzoptik | WUN-H2-E02-045 | FLOORING | Ku1 0.15 m | 1216Bfl0000045948/01 | m² | Bodenbelagsarbeiten | 1 | 0.15 | 0 | 1 | Bodenfläche | Ku1 | 0 | 0 | NEW | AllplanAttributes - Bezeichnung: PVC Bahnenware Holzoptik; Raumnr. Bauherr: 2.11_A2_02; ash B_Aufbau: B9; ash B_Rutschhemmung: R9
Acrovyn | WUN-H2-E02-045 | CLADDING | 84 0.001 m | 1216Sfl0812842692/02 | m² | Maler- und Lackierarbeiten | 2 | 0.001 | 0 | 1 | Seitenfläche | 84 | 0 | 0 | NEW | AllplanAttributes - Bezeichnung: Acrovyn
Acrovyn | WUN-H2-E02-045 | CLADDING | 84 0.001 m | 1216Sfl0812842722/02 | m² | Maler- und Lackierarbeiten | 2 | 0.001 | 0 | 1 | Seitenfläche | 84 | 0 | 0 | NEW | AllplanAttributes - Bezeichnung: Acrovyn
Gipsfaserplatten 2-lagig (BSK) | WUN-H2-E02-045 | CEILING | layer 0.036 m | 1216Dfl0000045949/01 | m² | Trockenbauarbeiten | 1 | 0.036 | 0 | 1 | Deckenfläche |  | 0 | 0 | NEW | 3.15 | AllplanAttributes - Bezeichnung: Gipsfaserplatten 2-lagig (BSK); ash_lichte Raumhöhe: 5.21803
 | WUN-H2-E02-045 | CEILING | A1 0.1 m | 1216Dfl0000045960/01 | m² | Trockenbauarbeiten | 1 | 0.1 | 0 | 1 | Bekleidung | A1 | 0 | 0 | NEW | 2.5 | AllplanAttributes - ash_lichte Raumhöhe: 2.5; OKFF: 0; Pset_CoveringCommon - AcousticRating: -
 | WUN-H2-E02-045 | CEILING | D1 0.001 m | 1216Dfl0000045960/02 | m² | Maler- und Lackierarbeiten | 2 | 0.001 | 0 | 1 | Bekleidung | D1 | 0 | 0 | NEW | AllplanAttributes - OKFF: 0
 | WUN-H2-E02-045 | CEILING | A1 0.1 m | 1216Dfl0813302867/01 | m² | Trockenbauarbeiten | 1 | 0.1 | 0 | 1 | Bekleidung | A1 | 0 | 0 | NEW | 2.5 | AllplanAttributes - ash_lichte Raumhöhe: 3.150000; OKFF: 0; Pset_CoveringCommon - AcousticRating: -
 | WUN-H2-E02-045 | CEILING | D1 0.001 m | 1216Dfl0813302867/02 | m² | Maler- und Lackierarbeiten | 2 | 0.001 | 0 | 1 | Bekleidung | D1 | 0 | 0 | NEW | 2.5 | AllplanAttributes - ash_lichte Raumhöhe: 3.150000; OKFF: 0
PVC Bahnenware Holzoptik | WUN-H2-E02-044 | FLOORING | Ku1 0.15 m | 1216Bfl0000045934/01 | m² | Bodenbelagsarbeiten | 1 | 0.15 | 0 | 1 | Bodenfläche | Ku1 | 0 | 0 | NEW | AllplanAttributes - Bezeichnung: PVC Bahnenware Holzoptik; Raumnr. Bauherr: 2.11_A2_02; ash B_Aufbau: B9; ash B_Rutschhemmung: R9
Acrovyn | WUN-H2-E02-044 | CLADDING | 84 0.001 m | 1216Sfl0812842690/02 | m² | Maler- und Lackierarbeiten | 2 | 0.001 | 0 | 1 | Seitenfläche | 84 | 0 | 0 | NEW | AllplanAttributes - Bezeichnung: Acrovyn
Gipsfaserplatten 2-lagig (BSK) | WUN-H2-E02-044 | CEILING | layer 0.036 m | 1216Dfl0000045935/01 | m² | Trockenbauarbeiten | 1 | 0.036 | 0 | 1 | Deckenfläche |  | 0 | 0 | NEW | 3.15 | AllplanAttributes - Bezeichnung: Gipsfaserplatten 2-lagig (BSK); ash_lichte Raumhöhe: 4.86395
 | WUN-H2-E02-044 | CEILING | A1 0.1 m | 1216Dfl0000045946/01 | m² | Trockenbauarbeiten | 1 | 0.1 | 0 | 1 | Bekleidung | A1 | 0 | 0 | NEW | 2.5 | AllplanAttributes - ash_lichte Raumhöhe: 2.5; OKFF: 0; Pset_CoveringCommon - AcousticRating: -
 | WUN-H2-E02-044 | CEILING | D1 0.001 m | 1216Dfl0000045946/02 | m² | Maler- und Lackierarbeiten | 2 | 0.001 | 0 | 1 | Bekleidung | D1 | 0 | 0 | NEW | AllplanAttributes - OKFF: 0
 | WUN-H2-E02-044 | CEILING | A1 0.1 m | 1216Dfl0813302576/01 | m² | Trockenbauarbeiten | 1 | 0.1 | 0 | 1 | Bekleidung | A1 | 0 | 0 | NEW | 2.5 | AllplanAttributes - ash_lichte Raumhöhe: 3.150000; OKFF: 0; Pset_CoveringCommon - AcousticRating: -
 | WUN-H2-E02-044 | CEILING | D1 0.001 m | 1216Dfl0813302576/02 | m² | Maler- und Lackierarbeiten | 2 | 0.001 | 0 | 1 | Bekleidung | D1 | 0 | 0 | NEW | 2.5 | AllplanAttributes - ash_lichte Raumhöhe: 3.150000; OKFF: 0
PVC Bahnenware Holzoptik | WUN-H2-E02-047 | FLOORING | Ku1 0.15 m | 1216Bfl0000046001/01 | m² | Bodenbelagsarbeiten | 1 | 0.15 | 0 | 1 | Bodenfläche | Ku1 | 0 | 0 | NEW | AllplanAttributes - Bezeichnung: PVC Bahnenware Holzoptik; Raumnr. Bauherr: 2.11_A2_02; ash B_Aufbau: B9; ash B_Rutschhemmung: R9
Acrovyn | WUN-H2-E02-047 | CLADDING | 84 0.001 m | 1216Sfl0812840222/02 | m² | Maler- und Lackierarbeiten | 2 | 0.001 | 0 | 1 | Seitenfläche | 84 | 0 | 0 | NEW | AllplanAttributes - Bezeichnung: Acrovyn
Gipsfaserplatten 2-lagig (BSK) | WUN-H2-E02-047 | CEILING | layer 0.036 m | 1216Dfl0000046000/01 | m² | Trockenbauarbeiten | 1 | 0.036 | 0 | 1 | Deckenfläche |  | 0 | 0 | NEW | 3.15 | AllplanAttributes - Bezeichnung: Gipsfaserplatten 2-lagig (BSK); ash_lichte Raumhöhe: 4.82718
 | WUN-H2-E02-047 | CEILING | A1 0.1 m | 1216Dfl0000046012/01 | m² | Trockenbauarbeiten | 1 | 0.1 | 0 | 1 | Bekleidung | A1 | 0 | 0 | NEW | 2.5 | AllplanAttributes - ash_lichte Raumhöhe: 2.5; OKFF: 0; Pset_CoveringCommon - AcousticRating: -
 | WUN-H2-E02-047 | CEILING | D1 0.001 m | 1216Dfl0000046012/02 | m² | Maler- und Lackierarbeiten | 2 | 0.001 | 0 | 1 | Bekleidung | D1 | 0 | 0 | NEW | AllplanAttributes - OKFF: 0
 | WUN-H2-E02-047 | CEILING | A1 0.1 m | 1216Dfl0813302584/01 | m² | Trockenbauarbeiten | 1 | 0.1 | 0 | 1 | Bekleidung | A1 | 0 | 0 | NEW | 2.5 | AllplanAttributes - ash_lichte Raumhöhe: 3.150000; OKFF: 0; Pset_CoveringCommon - AcousticRating: -
 | WUN-H2-E02-047 | CEILING | D1 0.001 m | 1216Dfl0813302584/02 | m² | Maler- und Lackierarbeiten | 2 | 0.001 | 0 | 1 | Bekleidung | D1 | 0 | 0 | NEW | 2.5 | AllplanAttributes - ash_lichte Raumhöhe: 3.150000; OKFF: 0
PVC Bahnenware Holzoptik | WUN-H2-E02-046 | FLOORING | Ku1 0.15 m | 1216Bfl0000045986/01 | m² | Bodenbelagsarbeiten | 1 | 0.15 | 0 | 1 | Bodenfläche | Ku1 | 0 | 0 | NEW | AllplanAttributes - Bezeichnung: PVC Bahnenware Holzoptik; Raumnr. Bauherr: 2.11_A2_02; ash B_Aufbau: B9; ash B_Rutschhemmung: R9
Acrovyn | WUN-H2-E02-046 | CLADDING | 84 0.001 m | 1216Sfl0812842694/02 | m² | Maler- und Lackierarbeiten | 2 | 0.001 | 0 | 1 | Seitenfläche | 84 | 0 | 0 | NEW | AllplanAttributes - Bezeichnung: Acrovyn
Acrovyn | WUN-H2-E02-046 | CLADDING | 84 0.001 m | 1216Sfl0812842720/02 | m² | Maler- und Lackierarbeiten | 2 | 0.001 | 0 | 1 | Seitenfläche | 84 | 0 | 0 | NEW | AllplanAttributes - Bezeichnung: Acrovyn
Gipsfaserplatten 2-lagig (BSK) | WUN-H2-E02-046 | CEILING | layer 0.036 m | 1216Dfl0000045987/01 | m² | Trockenbauarbeiten | 1 | 0.036 | 0 | 1 | Deckenfläche |  | 0 | 0 | NEW | 3.15 | AllplanAttributes - Bezeichnung: Gipsfaserplatten 2-lagig (BSK); ash_lichte Raumhöhe: 5.70777
 | WUN-H2-E02-046 | CEILING | A1 0.1 m | 1216Dfl0000045998/01 | m² | Trockenbauarbeiten | 1 | 0.1 | 0 | 1 | Bekleidung | A1 | 0 | 0 | NEW | 2.5 | AllplanAttributes - ash_lichte Raumhöhe: 2.5; OKFF: 0; Pset_CoveringCommon - AcousticRating: -
 | WUN-H2-E02-046 | CEILING | D1 0.001 m | 1216Dfl0000045998/02 | m² | Maler- und Lackierarbeiten | 2 | 0.001 | 0 | 1 | Bekleidung | D1 | 0 | 0 | NEW | AllplanAttributes - OKFF: 0
 | WUN-H2-E02-046 | CEILING | A1 0.1 m | 1216Dfl0813302580/01 | m² | Trockenbauarbeiten | 1 | 0.1 | 0 | 1 | Bekleidung | A1 | 0 | 0 | NEW | 2.5 | AllplanAttributes - ash_lichte Raumhöhe: 3.150000; OKFF: 0; Pset_CoveringCommon - AcousticRating: -
 | WUN-H2-E02-046 | CEILING | D1 0.001 m | 1216Dfl0813302580/02 | m² | Maler- und Lackierarbeiten | 2 | 0.001 | 0 | 1 | Bekleidung | D1 | 0 | 0 | NEW | 2.5 | AllplanAttributes - ash_lichte Raumhöhe: 3.150000; OKFF: 0
Fliesen | WUN-H2-E02-042a | FLOORING | Fl1 0.15 m | 1216Bfl0000045870/01 | m² | Bodenbelagsarbeiten | 1 | 0.15 | 0 | 1 | Bodenfläche | Fl1 | 0 | 0 | NEW | AllplanAttributes - Bezeichnung: Fliesen; Raumnr. Bauherr: 2.11_A2_02; ash B_Aufbau: B10; ash B_Rutschhemmung: R10
Fliesen Mosaik | WUN-H2-E02-042a | FLOORING | Fl2 0.15 m | 1216Bfl0813116065/01 | m² | Bodenbelagsarbeiten | 1 | 0.15 | 0 | 1 | Bodenfläche | Fl2 | 0 | 0 | NEW | AllplanAttributes - Bezeichnung: Fliesen Mosaik; Raumnr. Bauherr: 2.11_A2_02; ash B_Aufbau: B11; ash B_Rutschhemmung: R10; ash B_Bewertungsgruppe Barfußbereich: B
Gipsfaserplatten 2-lagig (BSK) | WUN-H2-E02-042a | CEILING | layer 0.036 m | 1216Dfl0000045871/01 | m² | Trockenbauarbeiten | 1 | 0.036 | 0 | 1 | Deckenfläche |  | 0 | 0 | NEW | 3.15 | AllplanAttributes - Bezeichnung: Gipsfaserplatten 2-lagig (BSK); ash_lichte Raumhöhe: 3.809
 | WUN-H2-E02-042a | CEILING | B 0.1 m | 1216Dfl0813301852/01 | m² | Trockenbauarbeiten | 1 | 0.1 | 0 | 1 | Bekleidung | B | 0 | 0 | NEW | 2.5 | AllplanAttributes - ash_lichte Raumhöhe: 2.5; OKFF: 0; Pset_CoveringCommon - AcousticRating: -
 | WUN-H2-E02-042a | CEILING | D1 0.001 m | 1216Dfl0813301852/02 | m² | Maler- und Lackierarbeiten | 2 | 0.001 | 0 | 1 | Bekleidung | D1 | 0 | 0 | NEW | AllplanAttributes - OKFF: 0
Fliesen | WUN-H2-E02-041a | FLOORING | Fl1 0.15 m | 1216Bfl0000045858/01 | m² | Bodenbelagsarbeiten | 1 | 0.15 | 0 | 1 | Bodenfläche | Fl1 | 0 | 0 | NEW | AllplanAttributes - Bezeichnung: Fliesen; Raumnr. Bauherr: 2.11_A2_02; ash B_Aufbau: B10; ash B_Rutschhemmung: R10
Fliesen Mosaik | WUN-H2-E02-041a | FLOORING | Fl2 0.15 m | 1216Bfl0813115864/01 | m² | Bodenbelagsarbeiten | 1 | 0.15 | 0 | 1 | Bodenfläche | Fl2 | 0 | 0 | NEW | AllplanAttributes - Bezeichnung: Fliesen Mosaik; Raumnr. Bauherr: 2.11_A2_02; ash B_Aufbau: B11; ash B_Rutschhemmung: R10; ash B_Bewertungsgruppe Barfußbereich: B
Gipsfaserplatten 2-lagig (BSK) | WUN-H2-E02-041a | CEILING | layer 0.036 m | 1216Dfl0000045859/01 | m² | Trockenbauarbeiten | 1 | 0.036 | 0 | 1 | Deckenfläche |  | 0 | 0 | NEW | 3.15 | AllplanAttributes - Bezeichnung: Gipsfaserplatten 2-lagig (BSK); ash_lichte Raumhöhe: 3.61648
 | WUN-H2-E02-041a | CEILING | B 0.1 m | 1216Dfl0813301849/01 | m² | Trockenbauarbeiten | 1 | 0.1 | 0 | 1 | Bekleidung | B | 0 | 0 | NEW | 2.5 | AllplanAttributes - ash_lichte Raumhöhe: 2.5; OKFF: 0; Pset_CoveringCommon - AcousticRating: -
 | WUN-H2-E02-041a | CEILING | D1 0.001 m | 1216Dfl0813301849/02 | m² | Maler- und Lackierarbeiten | 2 | 0.001 | 0 | 1 | Bekleidung | D1 | 0 | 0 | NEW | AllplanAttributes - OKFF: 0
Fliesen | WUN-H2-E02-044a | FLOORING | Fl1 0.15 m | 1216Bfl0000045922/01 | m² | Bodenbelagsarbeiten | 1 | 0.15 | 0 | 1 | Bodenfläche | Fl1 | 0 | 0 | NEW | AllplanAttributes - Bezeichnung: Fliesen; Raumnr. Bauherr: 2.11_A2_02; ash B_Aufbau: B10; ash B_Rutschhemmung: R10
Fliesen Mosaik | WUN-H2-E02-044a | FLOORING | Fl2 0.15 m | 1216Bfl0813116465/01 | m² | Bodenbelagsarbeiten | 1 | 0.15 | 0 | 1 | Bodenfläche | Fl2 | 0 | 0 | NEW | AllplanAttributes - Bezeichnung: Fliesen Mosaik; Raumnr. Bauherr: 2.11_A2_02; ash B_Aufbau: B11; ash B_Rutschhemmung: R10; ash B_Bewertungsgruppe Barfußbereich: B
Gipsfaserplatten 2-lagig (BSK) | WUN-H2-E02-044a | CEILING | layer 0.036 m | 1216Dfl0000045923/01 | m² | Trockenbauarbeiten | 1 | 0.036 | 0 | 1 | Deckenfläche |  | 0 | 0 | NEW | 3.15 | AllplanAttributes - Bezeichnung: Gipsfaserplatten 2-lagig (BSK); ash_lichte Raumhöhe: 4.74972
 | WUN-H2-E02-044a | CEILING | B 0.1 m | 1216Dfl0813301858/01 | m² | Trockenbauarbeiten | 1 | 0.1 | 0 | 1 | Bekleidung | B | 0 | 0 | NEW | 2.5 | AllplanAttributes - ash_lichte Raumhöhe: 2.5; OKFF: 0; Pset_CoveringCommon - AcousticRating: -
 | WUN-H2-E02-044a | CEILING | D1 0.001 m | 1216Dfl0813301858/02 | m² | Maler- und Lackierarbeiten | 2 | 0.001 | 0 | 1 | Bekleidung | D1 | 0 | 0 | NEW | AllplanAttributes - OKFF: 0
Fliesen | WUN-H2-E02-043a | FLOORING | Fl1 0.15 m | 1216Bfl0000045910/01 | m² | Bodenbelagsarbeiten | 1 | 0.15 | 0 | 1 | Bodenfläche | Fl1 | 0 | 0 | NEW | AllplanAttributes - Bezeichnung: Fliesen; Raumnr. Bauherr: 2.11_A2_02; ash B_Aufbau: B10; ash B_Rutschhemmung: R10
Fliesen Mosaik | WUN-H2-E02-043a | FLOORING | Fl2 0.15 m | 1216Bfl0813116265/01 | m² | Bodenbelagsarbeiten | 1 | 0.15 | 0 | 1 | Bodenfläche | Fl2 | 0 | 0 | NEW | AllplanAttributes - Bezeichnung: Fliesen Mosaik; Raumnr. Bauherr: 2.11_A2_02; ash B_Aufbau: B11; ash B_Rutschhemmung: R10; ash B_Bewertungsgruppe Barfußbereich: B
Gipsfaserplatten 2-lagig (BSK) | WUN-H2-E02-043a | CEILING | layer 0.036 m | 1216Dfl0000045911/01 | m² | Trockenbauarbeiten | 1 | 0.036 | 0 | 1 | Deckenfläche |  | 0 | 0 | NEW | 3.15 | AllplanAttributes - Bezeichnung: Gipsfaserplatten 2-lagig (BSK); ash_lichte Raumhöhe: 4.51891
 | WUN-H2-E02-043a | CEILING | B 0.1 m | 1216Dfl0813301855/01 | m² | Trockenbauarbeiten | 1 | 0.1 | 0 | 1 | Bekleidung | B | 0 | 0 | NEW | 2.5 | AllplanAttributes - ash_lichte Raumhöhe: 2.5; OKFF: 0; Pset_CoveringCommon - AcousticRating: -
 | WUN-H2-E02-043a | CEILING | D1 0.001 m | 1216Dfl0813301855/02 | m² | Maler- und Lackierarbeiten | 2 | 0.001 | 0 | 1 | Bekleidung | D1 | 0 | 0 | NEW | AllplanAttributes - OKFF: 0
Fliesen | WUN-H2-E02-045a | FLOORING | Fl1 0.15 m | 1216Bfl0000045962/01 | m² | Bodenbelagsarbeiten | 1 | 0.15 | 0 | 1 | Bodenfläche | Fl1 | 0 | 0 | NEW | AllplanAttributes - Bezeichnung: Fliesen; Raumnr. Bauherr: 2.11_A2_02; ash B_Aufbau: B10; ash B_Rutschhemmung: R10
Fliesen Mosaik | WUN-H2-E02-045a | FLOORING | Fl2 0.15 m | 1216Bfl0813116665/01 | m² | Bodenbelagsarbeiten | 1 | 0.15 | 0 | 1 | Bodenfläche | Fl2 | 0 | 0 | NEW | AllplanAttributes - Bezeichnung: Fliesen Mosaik; Raumnr. Bauherr: 2.11_A2_02; ash B_Aufbau: B11; ash B_Rutschhemmung: R10; ash B_Bewertungsgruppe Barfußbereich: B
Gipsfaserplatten 2-lagig (BSK) | WUN-H2-E02-045a | CEILING | layer 0.036 m | 1216Dfl0000045963/01 | m² | Trockenbauarbeiten | 1 | 0.036 | 0 | 1 | Deckenfläche |  | 0 | 0 | NEW | 3.15 | AllplanAttributes - Bezeichnung: Gipsfaserplatten 2-lagig (BSK); ash_lichte Raumhöhe: 5.36665
 | WUN-H2-E02-045a | CEILING | B 0.1 m | 1216Dfl0813301861/01 | m² | Trockenbauarbeiten | 1 | 0.1 | 0 | 1 | Bekleidung | B | 0 | 0 | NEW | 2.5 | AllplanAttributes - ash_lichte Raumhöhe: 2.5; OKFF: 0; Pset_CoveringCommon - AcousticRating: -
 | WUN-H2-E02-045a | CEILING | D1 0.001 m | 1216Dfl0813301861/02 | m² | Maler- und Lackierarbeiten | 2 | 0.001 | 0 | 1 | Bekleidung | D1 | 0 | 0 | NEW | AllplanAttributes - OKFF: 0
Fliesen | WUN-H2-E02-046a | FLOORING | Fl1 0.15 m | 1216Bfl0000045974/01 | m² | Bodenbelagsarbeiten | 1 | 0.15 | 0 | 1 | Bodenfläche | Fl1 | 0 | 0 | NEW | AllplanAttributes - Bezeichnung: Fliesen; Raumnr. Bauherr: 2.11_A2_02; ash B_Aufbau: B10; ash B_Rutschhemmung: R10
Fliesen Mosaik | WUN-H2-E02-046a | FLOORING | Fl2 0.15 m | 1216Bfl0813116865/01 | m² | Bodenbelagsarbeiten | 1 | 0.15 | 0 | 1 | Bodenfläche | Fl2 | 0 | 0 | NEW | AllplanAttributes - Bezeichnung: Fliesen Mosaik; Raumnr. Bauherr: 2.11_A2_02; ash B_Aufbau: B11; ash B_Rutschhemmung: R10; ash B_Bewertungsgruppe Barfußbereich: B
Gipsfaserplatten 2-lagig (BSK) | WUN-H2-E02-046a | CEILING | layer 0.036 m | 1216Dfl0000045975/01 | m² | Trockenbauarbeiten | 1 | 0.036 | 0 | 1 | Deckenfläche |  | 0 | 0 | NEW | 3.15 | AllplanAttributes - Bezeichnung: Gipsfaserplatten 2-lagig (BSK); ash_lichte Raumhöhe: 5.55917
 | WUN-H2-E02-046a | CEILING | B 0.1 m | 1216Dfl0813301864/01 | m² | Trockenbauarbeiten | 1 | 0.1 | 0 | 1 | Bekleidung | B | 0 | 0 | NEW | 2.5 | AllplanAttributes - ash_lichte Raumhöhe: 2.5; OKFF: 0; Pset_CoveringCommon - AcousticRating: -
 | WUN-H2-E02-046a | CEILING | D1 0.001 m | 1216Dfl0813301864/02 | m² | Maler- und Lackierarbeiten | 2 | 0.001 | 0 | 1 | Bekleidung | D1 | 0 | 0 | NEW | AllplanAttributes - OKFF: 0
Fliesen | WUN-H2-E02-047a | FLOORING | Fl1 0.15 m | 1216Bfl0000046014/01 | m² | Bodenbelagsarbeiten | 1 | 0.15 | 0 | 1 | Bodenfläche | Fl1 | 0 | 0 | NEW | AllplanAttributes - Bezeichnung: Fliesen; Raumnr. Bauherr: 2.11_A2_02; ash B_Aufbau: B10; ash B_Rutschhemmung: R10
Fliesen Mosaik | WUN-H2-E02-047a | FLOORING | Fl2 0.15 m | 1216Bfl0813117065/01 | m² | Bodenbelagsarbeiten | 1 | 0.15 | 0 | 1 | Bodenfläche | Fl2 | 0 | 0 | NEW | AllplanAttributes - Bezeichnung: Fliesen Mosaik; Raumnr. Bauherr: 2.11_A2_02; ash B_Aufbau: B11; ash B_Rutschhemmung: R10; ash B_Bewertungsgruppe Barfußbereich: B
Gipsfaserplatten 2-lagig (BSK) | WUN-H2-E02-047a | CEILING | layer 0.036 m | 1216Dfl0000046015/01 | m² | Trockenbauarbeiten | 1 | 0.036 | 0 | 1 | Deckenfläche |  | 0 | 0 | NEW | 3.15 | AllplanAttributes - Bezeichnung: Gipsfaserplatten 2-lagig (BSK); ash_lichte Raumhöhe: 4.55708
 | WUN-H2-E02-047a | CEILING | B 0.1 m | 1216Dfl0813301867/01 | m² | Trockenbauarbeiten | 1 | 0.1 | 0 | 1 | Bekleidung | B | 0 | 0 | NEW | 2.5 | AllplanAttributes - ash_lichte Raumhöhe: 2.5; OKFF: 0; Pset_CoveringCommon - AcousticRating: -
 | WUN-H2-E02-047a | CEILING | D1 0.001 m | 1216Dfl0813301867/02 | m² | Maler- und Lackierarbeiten | 2 | 0.001 | 0 | 1 | Bekleidung | D1 | 0 | 0 | NEW | AllplanAttributes - OKFF: 0
PVC Bahnenware Holzoptik | WUN-H2-E02-019 | FLOORING | Ku1 0.15 m | 1216Bfl0000046359/01 | m² | Bodenbelagsarbeiten | 1 | 0.15 | 0 | 1 | Bodenfläche | Ku1 | 0 | 0 | NEW | AllplanAttributes - Bezeichnung: PVC Bahnenware Holzoptik; Raumnr. Bauherr: 2.11_A2_02; ash B_Aufbau: B9; ash B_Rutschhemmung: R9
Acrovyn | WUN-H2-E02-019 | CLADDING | 84 0.001 m | 1216Sfl0812842770/02 | m² | Maler- und Lackierarbeiten | 2 | 0.001 | 0 | 1 | Seitenfläche | 84 | 0 | 0 | NEW | AllplanAttributes - Bezeichnung: Acrovyn
Acrovyn | WUN-H2-E02-019 | CLADDING | 84 0.001 m | 1216Sfl0812842741/02 | m² | Maler- und Lackierarbeiten | 2 | 0.001 | 0 | 1 | Seitenfläche | 84 | 0 | 0 | NEW | AllplanAttributes - Bezeichnung: Acrovyn
 | WUN-H2-E02-019 | CEILING | A1 0.1 m | 1216Dfl0000046370/01 | m² | Trockenbauarbeiten | 1 | 0.1 | 0 | 1 | Bekleidung | A1 | 0 | 0 | NEW | 2.5 | AllplanAttributes - ash_lichte Raumhöhe: 2.5; OKFF: 0; Pset_CoveringCommon - AcousticRating: -
 | WUN-H2-E02-019 | CEILING | D1 0.001 m | 1216Dfl0000046370/02 | m² | Maler- und Lackierarbeiten | 2 | 0.001 | 0 | 1 | Bekleidung | D1 | 0 | 0 | NEW | AllplanAttributes - OKFF: 0
Gipsfaserplatten 2-lagig (BSK) | WUN-H2-E02-019 | CEILING | layer 0.036 m | 1216Dfl0000046358/01 | m² | Trockenbauarbeiten | 1 | 0.036 | 0 | 1 | Deckenfläche |  | 0 | 0 | NEW | 3.15 | AllplanAttributes - Bezeichnung: Gipsfaserplatten 2-lagig (BSK); ash_lichte Raumhöhe: 4.81928
 | WUN-H2-E02-019 | CEILING | A1 0.1 m | 1216Dfl0813301074/01 | m² | Trockenbauarbeiten | 1 | 0.1 | 0 | 1 | Bekleidung | A1 | 0 | 0 | NEW | 2.5 | AllplanAttributes - ash_lichte Raumhöhe: 3.150000; OKFF: 0; Pset_CoveringCommon - AcousticRating: -
 | WUN-H2-E02-019 | CEILING | D1 0.001 m | 1216Dfl0813301074/02 | m² | Maler- und Lackierarbeiten | 2 | 0.001 | 0 | 1 | Bekleidung | D1 | 0 | 0 | NEW | 2.5 | AllplanAttributes - ash_lichte Raumhöhe: 3.150000; OKFF: 0
PVC Bahnenware Holzoptik | WUN-H2-E02-024 | FLOORING | Ku1 0.15 m | 1216Bfl0000046228/01 | m² | Bodenbelagsarbeiten | 1 | 0.15 | 0 | 1 | Bodenfläche | Ku1 | 0 | 0 | NEW | AllplanAttributes - Bezeichnung: PVC Bahnenware Holzoptik; Raumnr. Bauherr: 2.11_A2_02; ash B_Aufbau: B9; ash B_Rutschhemmung: R9
Acrovyn | WUN-H2-E02-024 | CLADDING | 84 0.001 m | 1216Sfl0812842778/02 | m² | Maler- und Lackierarbeiten | 2 | 0.001 | 0 | 1 | Seitenfläche | 84 | 0 | 0 | NEW | AllplanAttributes - Bezeichnung: Acrovyn
Acrovyn | WUN-H2-E02-024 | CLADDING | 84 0.001 m | 1216Sfl0812842729/02 | m² | Maler- und Lackierarbeiten | 2 | 0.001 | 0 | 1 | Seitenfläche | 84 | 0 | 0 | NEW | AllplanAttributes - Bezeichnung: Acrovyn
 | WUN-H2-E02-024 | CEILING | A1 0.1 m | 1216Dfl0000046240/01 | m² | Trockenbauarbeiten | 1 | 0.1 | 0 | 1 | Bekleidung | A1 | 0 | 0 | NEW | 2.5 | AllplanAttributes - ash_lichte Raumhöhe: 2.5; OKFF: 0; Pset_CoveringCommon - AcousticRating: -
 | WUN-H2-E02-024 | CEILING | D1 0.001 m | 1216Dfl0000046240/02 | m² | Maler- und Lackierarbeiten | 2 | 0.001 | 0 | 1 | Bekleidung | D1 | 0 | 0 | NEW | AllplanAttributes - OKFF: 0
 | WUN-H2-E02-024 | CEILING | A1 0.1 m | 1216Dfl0813301020/01 | m² | Trockenbauarbeiten | 1 | 0.1 | 0 | 1 | Bekleidung | A1 | 0 | 0 | NEW | 2.5 | AllplanAttributes - ash_lichte Raumhöhe: 3.150000; OKFF: 0; Pset_CoveringCommon - AcousticRating: -
 | WUN-H2-E02-024 | CEILING | D1 0.001 m | 1216Dfl0813301020/02 | m² | Maler- und Lackierarbeiten | 2 | 0.001 | 0 | 1 | Bekleidung | D1 | 0 | 0 | NEW | 2.5 | AllplanAttributes - ash_lichte Raumhöhe: 3.150000; OKFF: 0
Gipsfaserplatten 2-lagig (BSK) | WUN-H2-E02-024 | CEILING | layer 0.036 m | 1216Dfl0000046229/01 | m² | Trockenbauarbeiten | 1 | 0.036 | 0 | 1 | Deckenfläche |  | 0 | 0 | NEW | 3.15 | AllplanAttributes - Bezeichnung: Gipsfaserplatten 2-lagig (BSK); ash_lichte Raumhöhe: 3.95763
PVC Bahnenware Holzoptik | WUN-H2-E02-023 | FLOORING | Ku1 0.15 m | 1216Bfl0000046254/01 | m² | Bodenbelagsarbeiten | 1 | 0.15 | 0 | 1 | Bodenfläche | Ku1 | 0 | 0 | NEW | AllplanAttributes - Bezeichnung: PVC Bahnenware Holzoptik; Raumnr. Bauherr: 2.11_A2_02; ash B_Aufbau: B9; ash B_Rutschhemmung: R9
Acrovyn | WUN-H2-E02-023 | CLADDING | 84 0.001 m | 1216Sfl0812842776/02 | m² | Maler- und Lackierarbeiten | 2 | 0.001 | 0 | 1 | Seitenfläche | 84 | 0 | 0 | NEW | AllplanAttributes - Bezeichnung: Acrovyn
Acrovyn | WUN-H2-E02-023 | CLADDING | 84 0.001 m | 1216Sfl0812842733/02 | m² | Maler- und Lackierarbeiten | 2 | 0.001 | 0 | 1 | Seitenfläche | 84 | 0 | 0 | NEW | AllplanAttributes - Bezeichnung: Acrovyn
 | WUN-H2-E02-023 | CEILING | A1 0.1 m | 1216Dfl0000046266/01 | m² | Trockenbauarbeiten | 1 | 0.1 | 0 | 1 | Bekleidung | A1 | 0 | 0 | NEW | 2.5 | AllplanAttributes - ash_lichte Raumhöhe: 2.5; OKFF: 0; Pset_CoveringCommon - AcousticRating: -
 | WUN-H2-E02-023 | CEILING | D1 0.001 m | 1216Dfl0000046266/02 | m² | Maler- und Lackierarbeiten | 2 | 0.001 | 0 | 1 | Bekleidung | D1 | 0 | 0 | NEW | AllplanAttributes - OKFF: 0
Gipsfaserplatten 2-lagig (BSK) | WUN-H2-E02-023 | CEILING | layer 0.036 m | 1216Dfl0000046255/01 | m² | Trockenbauarbeiten | 1 | 0.036 | 0 | 1 | Deckenfläche |  | 0 | 0 | NEW | 3.15 | AllplanAttributes - Bezeichnung: Gipsfaserplatten 2-lagig (BSK); ash_lichte Raumhöhe: 4.36909
 | WUN-H2-E02-023 | CEILING | A1 0.1 m | 1216Dfl0813301024/01 | m² | Trockenbauarbeiten | 1 | 0.1 | 0 | 1 | Bekleidung | A1 | 0 | 0 | NEW | 2.5 | AllplanAttributes - ash_lichte Raumhöhe: 3.150000; OKFF: 0; Pset_CoveringCommon - AcousticRating: -
 | WUN-H2-E02-023 | CEILING | D1 0.001 m | 1216Dfl0813301024/02 | m² | Maler- und Lackierarbeiten | 2 | 0.001 | 0 | 1 | Bekleidung | D1 | 0 | 0 | NEW | 2.5 | AllplanAttributes - ash_lichte Raumhöhe: 3.150000; OKFF: 0
PVC Bahnenware Holzoptik | WUN-H2-E02-022 | FLOORING | Ku1 0.15 m | 1216Bfl0000046292/01 | m² | Bodenbelagsarbeiten | 1 | 0.15 | 0 | 1 | Bodenfläche | Ku1 | 0 | 0 | NEW | AllplanAttributes - Bezeichnung: PVC Bahnenware Holzoptik; Raumnr. Bauherr: 2.11_A2_02; ash B_Aufbau: B9; ash B_Rutschhemmung: R9
Acrovyn | WUN-H2-E02-022 | CLADDING | 84 0.001 m | 1216Sfl0812842735/02 | m² | Maler- und Lackierarbeiten | 2 | 0.001 | 0 | 1 | Seitenfläche | 84 | 0 | 0 | NEW | AllplanAttributes - Bezeichnung: Acrovyn
Gipsfaserplatten 2-lagig (BSK) | WUN-H2-E02-022 | CEILING | layer 0.036 m | 1216Dfl0000046293/01 | m² | Trockenbauarbeiten | 1 | 0.036 | 0 | 1 | Deckenfläche |  | 0 | 0 | NEW | 3.15 | AllplanAttributes - Bezeichnung: Gipsfaserplatten 2-lagig (BSK); ash_lichte Raumhöhe: 4.86396
 | WUN-H2-E02-022 | CEILING | A1 0.1 m | 1216Dfl0000046304/01 | m² | Trockenbauarbeiten | 1 | 0.1 | 0 | 1 | Bekleidung | A1 | 0 | 0 | NEW | 2.5 | AllplanAttributes - ash_lichte Raumhöhe: 2.5; OKFF: 0; Pset_CoveringCommon - AcousticRating: -
 | WUN-H2-E02-022 | CEILING | D1 0.001 m | 1216Dfl0000046304/02 | m² | Maler- und Lackierarbeiten | 2 | 0.001 | 0 | 1 | Bekleidung | D1 | 0 | 0 | NEW | AllplanAttributes - OKFF: 0
 | WUN-H2-E02-022 | CEILING | A1 0.1 m | 1216Dfl0813301028/01 | m² | Trockenbauarbeiten | 1 | 0.1 | 0 | 1 | Bekleidung | A1 | 0 | 0 | NEW | 2.5 | AllplanAttributes - ash_lichte Raumhöhe: 3.150000; OKFF: 0; Pset_CoveringCommon - AcousticRating: -
 | WUN-H2-E02-022 | CEILING | D1 0.001 m | 1216Dfl0813301028/02 | m² | Maler- und Lackierarbeiten | 2 | 0.001 | 0 | 1 | Bekleidung | D1 | 0 | 0 | NEW | 2.5 | AllplanAttributes - ash_lichte Raumhöhe: 3.150000; OKFF: 0
PVC Bahnenware Holzoptik | WUN-H2-E02-021 | FLOORING | Ku1 0.15 m | 1216Bfl0000046306/01 | m² | Bodenbelagsarbeiten | 1 | 0.15 | 0 | 1 | Bodenfläche | Ku1 | 0 | 0 | NEW | AllplanAttributes - Bezeichnung: PVC Bahnenware Holzoptik; Raumnr. Bauherr: 2.11_A2_02; ash B_Aufbau: B9; ash B_Rutschhemmung: R9
Acrovyn | WUN-H2-E02-021 | CLADDING | 84 0.001 m | 1216Sfl0812842774/02 | m² | Maler- und Lackierarbeiten | 2 | 0.001 | 0 | 1 | Seitenfläche | 84 | 0 | 0 | NEW | AllplanAttributes - Bezeichnung: Acrovyn
Acrovyn | WUN-H2-E02-021 | CLADDING | 84 0.001 m | 1216Sfl0812842737/02 | m² | Maler- und Lackierarbeiten | 2 | 0.001 | 0 | 1 | Seitenfläche | 84 | 0 | 0 | NEW | AllplanAttributes - Bezeichnung: Acrovyn
Gipsfaserplatten 2-lagig (BSK) | WUN-H2-E02-021 | CEILING | layer 0.036 m | 1216Dfl0000046307/01 | m² | Trockenbauarbeiten | 1 | 0.036 | 0 | 1 | Deckenfläche |  | 0 | 0 | NEW | 3.15 | AllplanAttributes - Bezeichnung: Gipsfaserplatten 2-lagig (BSK); ash_lichte Raumhöhe: 5.21802
 | WUN-H2-E02-021 | CEILING | A1 0.1 m | 1216Dfl0000046318/01 | m² | Trockenbauarbeiten | 1 | 0.1 | 0 | 1 | Bekleidung | A1 | 0 | 0 | NEW | 2.5 | AllplanAttributes - ash_lichte Raumhöhe: 2.5; OKFF: 0; Pset_CoveringCommon - AcousticRating: -
 | WUN-H2-E02-021 | CEILING | D1 0.001 m | 1216Dfl0000046318/02 | m² | Maler- und Lackierarbeiten | 2 | 0.001 | 0 | 1 | Bekleidung | D1 | 0 | 0 | NEW | AllplanAttributes - OKFF: 0
 | WUN-H2-E02-021 | CEILING | A1 0.1 m | 1216Dfl0813301066/01 | m² | Trockenbauarbeiten | 1 | 0.1 | 0 | 1 | Bekleidung | A1 | 0 | 0 | NEW | 2.5 | AllplanAttributes - ash_lichte Raumhöhe: 3.150000; OKFF: 0; Pset_CoveringCommon - AcousticRating: -
 | WUN-H2-E02-021 | CEILING | D1 0.001 m | 1216Dfl0813301066/02 | m² | Maler- und Lackierarbeiten | 2 | 0.001 | 0 | 1 | Bekleidung | D1 | 0 | 0 | NEW | 2.5 | AllplanAttributes - ash_lichte Raumhöhe: 3.150000; OKFF: 0
PVC Bahnenware Holzoptik | WUN-H2-E02-020 | FLOORING | Ku1 0.15 m | 1216Bfl0000046344/01 | m² | Bodenbelagsarbeiten | 1 | 0.15 | 0 | 1 | Bodenfläche | Ku1 | 0 | 0 | NEW | AllplanAttributes - Bezeichnung: PVC Bahnenware Holzoptik; Raumnr. Bauherr: 2.11_A2_02; ash B_Aufbau: B9; ash B_Rutschhemmung: R9
Acrovyn | WUN-H2-E02-020 | CLADDING | 84 0.001 m | 1216Sfl0812842772/02 | m² | Maler- und Lackierarbeiten | 2 | 0.001 | 0 | 1 | Seitenfläche | 84 | 0 | 0 | NEW | AllplanAttributes - Bezeichnung: Acrovyn
Acrovyn | WUN-H2-E02-020 | CLADDING | 84 0.001 m | 1216Sfl0812842739/02 | m² | Maler- und Lackierarbeiten | 2 | 0.001 | 0 | 1 | Seitenfläche | 84 | 0 | 0 | NEW | AllplanAttributes - Bezeichnung: Acrovyn
 | WUN-H2-E02-020 | CEILING | A1 0.1 m | 1216Dfl0000046356/01 | m² | Trockenbauarbeiten | 1 | 0.1 | 0 | 1 | Bekleidung | A1 | 0 | 0 | NEW | 2.5 | AllplanAttributes - ash_lichte Raumhöhe: 2.5; OKFF: 0; Pset_CoveringCommon - AcousticRating: -
 | WUN-H2-E02-020 | CEILING | D1 0.001 m | 1216Dfl0000046356/02 | m² | Maler- und Lackierarbeiten | 2 | 0.001 | 0 | 1 | Bekleidung | D1 | 0 | 0 | NEW | AllplanAttributes - OKFF: 0
Gipsfaserplatten 2-lagig (BSK) | WUN-H2-E02-020 | CEILING | layer 0.036 m | 1216Dfl0000046345/01 | m² | Trockenbauarbeiten | 1 | 0.036 | 0 | 1 | Deckenfläche |  | 0 | 0 | NEW | 3.15 | AllplanAttributes - Bezeichnung: Gipsfaserplatten 2-lagig (BSK); ash_lichte Raumhöhe: 5.70778
 | WUN-H2-E02-020 | CEILING | A1 0.1 m | 1216Dfl0813301070/01 | m² | Trockenbauarbeiten | 1 | 0.1 | 0 | 1 | Bekleidung | A1 | 0 | 0 | NEW | 2.5 | AllplanAttributes - ash_lichte Raumhöhe: 3.150000; OKFF: 0; Pset_CoveringCommon - AcousticRating: -
 | WUN-H2-E02-020 | CEILING | D1 0.001 m | 1216Dfl0813301070/02 | m² | Maler- und Lackierarbeiten | 2 | 0.001 | 0 | 1 | Bekleidung | D1 | 0 | 0 | NEW | 2.5 | AllplanAttributes - ash_lichte Raumhöhe: 3.150000; OKFF: 0
Fliesen | WUN-H2-E02-019a | FLOORING | Fl1 0.15 m | 1216Bfl0000046372/01 | m² | Bodenbelagsarbeiten | 1 | 0.15 | 0 | 1 | Bodenfläche | Fl1 | 0 | 0 | NEW | AllplanAttributes - Bezeichnung: Fliesen; Raumnr. Bauherr: 2.11_A2_02; ash B_Aufbau: B10; ash B_Rutschhemmung: R10
Fliesen Mosaik | WUN-H2-E02-019a | FLOORING | Fl2 0.15 m | 1216Bfl0813115464/01 | m² | Bodenbelagsarbeiten | 1 | 0.15 | 0 | 1 | Bodenfläche | Fl2 | 0 | 0 | NEW | AllplanAttributes - Bezeichnung: Fliesen Mosaik; Raumnr. Bauherr: 2.11_A2_02; ash B_Aufbau: B11; ash B_Rutschhemmung: R10; ash B_Bewertungsgruppe Barfußbereich: B
Gipsfaserplatten 2-lagig (BSK) | WUN-H2-E02-019a | CEILING | layer 0.036 m | 1216Dfl0000046373/01 | m² | Trockenbauarbeiten | 1 | 0.036 | 0 | 1 | Deckenfläche |  | 0 | 0 | NEW | 3.15 | AllplanAttributes - Bezeichnung: Gipsfaserplatten 2-lagig (BSK); ash_lichte Raumhöhe: 4.43822
 | WUN-H2-E02-019a | CEILING | B 0.1 m | 1216Dfl0813300481/01 | m² | Trockenbauarbeiten | 1 | 0.1 | 0 | 1 | Bekleidung | B | 0 | 0 | NEW | 2.5 | AllplanAttributes - ash_lichte Raumhöhe: 2.5; OKFF: 0; Pset_CoveringCommon - AcousticRating: -
 | WUN-H2-E02-019a | CEILING | D1 0.001 m | 1216Dfl0813300481/02 | m² | Maler- und Lackierarbeiten | 2 | 0.001 | 0 | 1 | Bekleidung | D1 | 0 | 0 | NEW | AllplanAttributes - OKFF: 0
Fliesen | WUN-H2-E02-025a | FLOORING | Fl1 0.15 m | 1216Bfl0000046216/01 | m² | Bodenbelagsarbeiten | 1 | 0.15 | 0 | 1 | Bodenfläche | Fl1 | 0 | 0 | NEW | AllplanAttributes - Bezeichnung: Fliesen; Raumnr. Bauherr: 2.11_A2_02; ash B_Aufbau: B10; ash B_Rutschhemmung: R10
Fliesen Mosaik | WUN-H2-E02-025a | FLOORING | Fl2 0.15 m | 1216Bfl0813114264/01 | m² | Bodenbelagsarbeiten | 1 | 0.15 | 0 | 1 | Bodenfläche | Fl2 | 0 | 0 | NEW | AllplanAttributes - Bezeichnung: Fliesen Mosaik; Raumnr. Bauherr: 2.11_A2_02; ash B_Aufbau: B11; ash B_Rutschhemmung: R10; ash B_Bewertungsgruppe Barfußbereich: B
Gipsfaserplatten 2-lagig (BSK) | WUN-H2-E02-025a | CEILING | layer 0.036 m | 1216Dfl0000046217/01 | m² | Trockenbauarbeiten | 1 | 0.036 | 0 | 1 | Deckenfläche |  | 0 | 0 | NEW | 3.15 | AllplanAttributes - Bezeichnung: Gipsfaserplatten 2-lagig (BSK); ash_lichte Raumhöhe: 3.61648
 | WUN-H2-E02-025a | CEILING | B 0.1 m | 1216Dfl0813300043/01 | m² | Trockenbauarbeiten | 1 | 0.1 | 0 | 1 | Bekleidung | B | 0 | 0 | NEW | 2.5 | AllplanAttributes - ash_lichte Raumhöhe: 2.5; OKFF: 0; Pset_CoveringCommon - AcousticRating: -
 | WUN-H2-E02-025a | CEILING | D1 0.001 m | 1216Dfl0813300043/02 | m² | Maler- und Lackierarbeiten | 2 | 0.001 | 0 | 1 | Bekleidung | D1 | 0 | 0 | NEW | AllplanAttributes - OKFF: 0
Fliesen | WUN-H2-E02-024a | FLOORING | Fl1 0.15 m | 1216Bfl0000046242/01 | m² | Bodenbelagsarbeiten | 1 | 0.15 | 0 | 1 | Bodenfläche | Fl1 | 0 | 0 | NEW | AllplanAttributes - Bezeichnung: Fliesen; Raumnr. Bauherr: 2.11_A2_02; ash B_Aufbau: B10; ash B_Rutschhemmung: R10
Fliesen Mosaik | WUN-H2-E02-024a | FLOORING | Fl2 0.15 m | 1216Bfl0813114464/01 | m² | Bodenbelagsarbeiten | 1 | 0.15 | 0 | 1 | Bodenfläche | Fl2 | 0 | 0 | NEW | AllplanAttributes - Bezeichnung: Fliesen Mosaik; Raumnr. Bauherr: 2.11_A2_02; ash B_Aufbau: B11; ash B_Rutschhemmung: R10; ash B_Bewertungsgruppe Barfußbereich: B
Gipsfaserplatten 2-lagig (BSK) | WUN-H2-E02-024a | CEILING | layer 0.036 m | 1216Dfl0000046243/01 | m² | Trockenbauarbeiten | 1 | 0.036 | 0 | 1 | Deckenfläche |  | 0 | 0 | NEW | 3.15 | AllplanAttributes - Bezeichnung: Gipsfaserplatten 2-lagig (BSK); ash_lichte Raumhöhe: 3.809
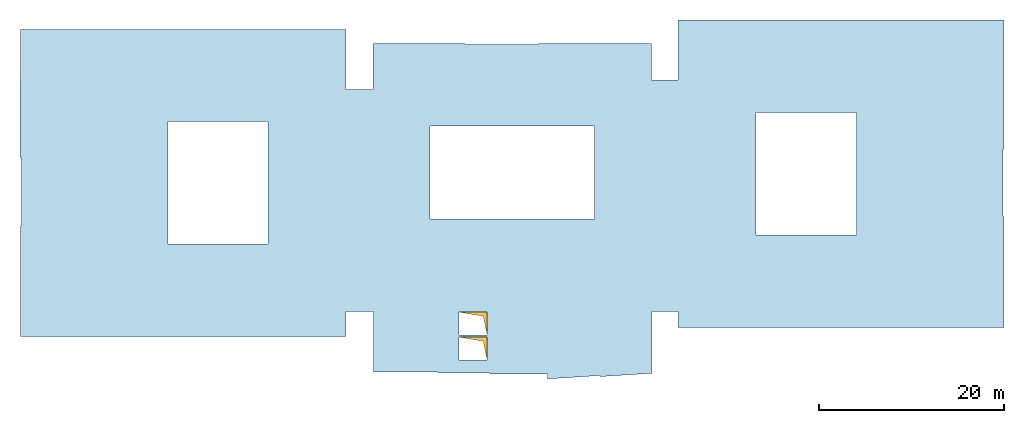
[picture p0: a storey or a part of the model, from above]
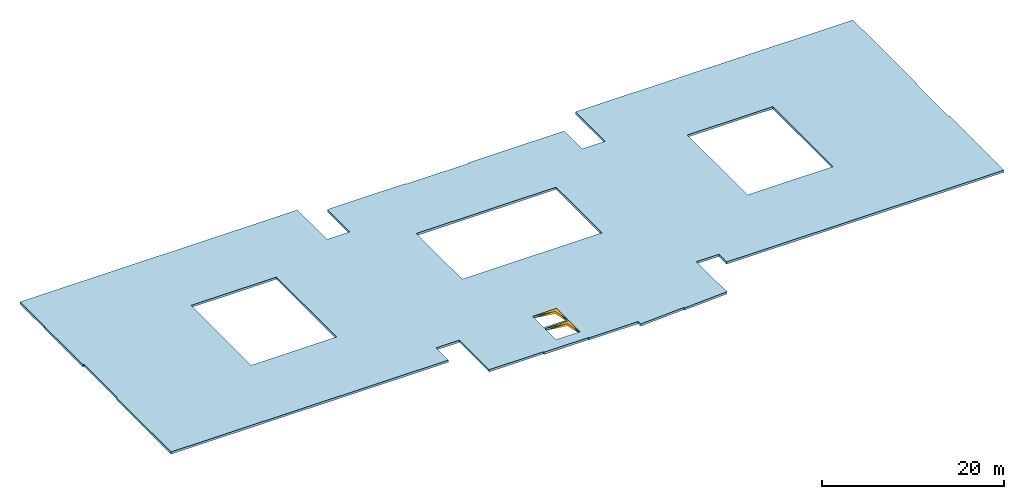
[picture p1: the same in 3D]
Properties of the parts of a building model (IFC4), part 8 of 80

# IfcCovering (3945)
Name | In | PredefinedType | Material | Allright_Bauteil_ID | Abrechnungsart | Gewerk | Schichtnummer | Schichtdicke (m) | Dicke (m) | Faktor | Objektname | AllplanAttributes, Material | Bezugshöhe | Deltahöhe | Status | D_lichte Raumhöhe [Zahl] (m)
 | WUN-H2-E02-024a | CEILING | B 0.1 m | 1216Dfl0813300116/01 | m² | Trockenbauarbeiten | 1 | 0.1 | 0 | 1 | Bekleidung | B | 0 | 0 | NEW | 2.5 | AllplanAttributes - ash_lichte Raumhöhe: 2.5; OKFF: 0; Pset_CoveringCommon - AcousticRating: -
 | WUN-H2-E02-024a | CEILING | D1 0.001 m | 1216Dfl0813300116/02 | m² | Maler- und Lackierarbeiten | 2 | 0.001 | 0 | 1 | Bekleidung | D1 | 0 | 0 | NEW | AllplanAttributes - OKFF: 0
Fliesen | WUN-H2-E02-023a | FLOORING | Fl1 0.15 m | 1216Bfl0000046268/01 | m² | Bodenbelagsarbeiten | 1 | 0.15 | 0 | 1 | Bodenfläche | Fl1 | 0 | 0 | NEW | AllplanAttributes - Bezeichnung: Fliesen; Raumnr. Bauherr: 2.11_A2_02; ash B_Aufbau: B10; ash B_Rutschhemmung: R10
Fliesen Mosaik | WUN-H2-E02-023a | FLOORING | Fl2 0.15 m | 1216Bfl0813114664/01 | m² | Bodenbelagsarbeiten | 1 | 0.15 | 0 | 1 | Bodenfläche | Fl2 | 0 | 0 | NEW | AllplanAttributes - Bezeichnung: Fliesen Mosaik; Raumnr. Bauherr: 2.11_A2_02; ash B_Aufbau: B11; ash B_Rutschhemmung: R10; ash B_Bewertungsgruppe Barfußbereich: B
Gipsfaserplatten 2-lagig (BSK) | WUN-H2-E02-023a | CEILING | layer 0.036 m | 1216Dfl0000046269/01 | m² | Trockenbauarbeiten | 1 | 0.036 | 0 | 1 | Deckenfläche |  | 0 | 0 | NEW | 3.15 | AllplanAttributes - Bezeichnung: Gipsfaserplatten 2-lagig (BSK); ash_lichte Raumhöhe: 4.51891
 | WUN-H2-E02-023a | CEILING | B 0.1 m | 1216Dfl0813300189/01 | m² | Trockenbauarbeiten | 1 | 0.1 | 0 | 1 | Bekleidung | B | 0 | 0 | NEW | 2.5 | AllplanAttributes - ash_lichte Raumhöhe: 2.5; OKFF: 0; Pset_CoveringCommon - AcousticRating: -
 | WUN-H2-E02-023a | CEILING | D1 0.001 m | 1216Dfl0813300189/02 | m² | Maler- und Lackierarbeiten | 2 | 0.001 | 0 | 1 | Bekleidung | D1 | 0 | 0 | NEW | AllplanAttributes - OKFF: 0
Fliesen | WUN-H2-E02-022a | FLOORING | Fl1 0.15 m | 1216Bfl0000046280/01 | m² | Bodenbelagsarbeiten | 1 | 0.15 | 0 | 1 | Bodenfläche | Fl1 | 0 | 0 | NEW | AllplanAttributes - Bezeichnung: Fliesen; Raumnr. Bauherr: 2.11_A2_02; ash B_Aufbau: B10; ash B_Rutschhemmung: R10
Fliesen Mosaik | WUN-H2-E02-022a | FLOORING | Fl2 0.15 m | 1216Bfl0813114864/01 | m² | Bodenbelagsarbeiten | 1 | 0.15 | 0 | 1 | Bodenfläche | Fl2 | 0 | 0 | NEW | AllplanAttributes - Bezeichnung: Fliesen Mosaik; Raumnr. Bauherr: 2.11_A2_02; ash B_Aufbau: B11; ash B_Rutschhemmung: R10; ash B_Bewertungsgruppe Barfußbereich: B
Gipsfaserplatten 2-lagig (BSK) | WUN-H2-E02-022a | CEILING | layer 0.036 m | 1216Dfl0000046281/01 | m² | Trockenbauarbeiten | 1 | 0.036 | 0 | 1 | Deckenfläche |  | 0 | 0 | NEW | 3.15 | AllplanAttributes - Bezeichnung: Gipsfaserplatten 2-lagig (BSK); ash_lichte Raumhöhe: 4.74972
 | WUN-H2-E02-022a | CEILING | B 0.1 m | 1216Dfl0813300262/01 | m² | Trockenbauarbeiten | 1 | 0.1 | 0 | 1 | Bekleidung | B | 0 | 0 | NEW | 2.5 | AllplanAttributes - ash_lichte Raumhöhe: 2.5; OKFF: 0; Pset_CoveringCommon - AcousticRating: -
 | WUN-H2-E02-022a | CEILING | D1 0.001 m | 1216Dfl0813300262/02 | m² | Maler- und Lackierarbeiten | 2 | 0.001 | 0 | 1 | Bekleidung | D1 | 0 | 0 | NEW | AllplanAttributes - OKFF: 0
Fliesen | WUN-H2-E02-021a | FLOORING | Fl1 0.15 m | 1216Bfl0000046320/01 | m² | Bodenbelagsarbeiten | 1 | 0.15 | 0 | 1 | Bodenfläche | Fl1 | 0 | 0 | NEW | AllplanAttributes - Bezeichnung: Fliesen; Raumnr. Bauherr: 2.11_A2_02; ash B_Aufbau: B10; ash B_Rutschhemmung: R10
Fliesen Mosaik | WUN-H2-E02-021a | FLOORING | Fl2 0.15 m | 1216Bfl0813115064/01 | m² | Bodenbelagsarbeiten | 1 | 0.15 | 0 | 1 | Bodenfläche | Fl2 | 0 | 0 | NEW | AllplanAttributes - Bezeichnung: Fliesen Mosaik; Raumnr. Bauherr: 2.11_A2_02; ash B_Aufbau: B11; ash B_Rutschhemmung: R10; ash B_Bewertungsgruppe Barfußbereich: B
Gipsfaserplatten 2-lagig (BSK) | WUN-H2-E02-021a | CEILING | layer 0.036 m | 1216Dfl0000046321/01 | m² | Trockenbauarbeiten | 1 | 0.036 | 0 | 1 | Deckenfläche |  | 0 | 0 | NEW | 3.15 | AllplanAttributes - Bezeichnung: Gipsfaserplatten 2-lagig (BSK); ash_lichte Raumhöhe: 5.36665
 | WUN-H2-E02-021a | CEILING | B 0.1 m | 1216Dfl0813300335/01 | m² | Trockenbauarbeiten | 1 | 0.1 | 0 | 1 | Bekleidung | B | 0 | 0 | NEW | 2.5 | AllplanAttributes - ash_lichte Raumhöhe: 2.5; OKFF: 0; Pset_CoveringCommon - AcousticRating: -
 | WUN-H2-E02-021a | CEILING | D1 0.001 m | 1216Dfl0813300335/02 | m² | Maler- und Lackierarbeiten | 2 | 0.001 | 0 | 1 | Bekleidung | D1 | 0 | 0 | NEW | AllplanAttributes - OKFF: 0
Fliesen | WUN-H2-E02-020a | FLOORING | Fl1 0.15 m | 1216Bfl0000046332/01 | m² | Bodenbelagsarbeiten | 1 | 0.15 | 0 | 1 | Bodenfläche | Fl1 | 0 | 0 | NEW | AllplanAttributes - Bezeichnung: Fliesen; Raumnr. Bauherr: 2.11_A2_02; ash B_Aufbau: B10; ash B_Rutschhemmung: R10
Fliesen Mosaik | WUN-H2-E02-020a | FLOORING | Fl2 0.15 m | 1216Bfl0813115264/01 | m² | Bodenbelagsarbeiten | 1 | 0.15 | 0 | 1 | Bodenfläche | Fl2 | 0 | 0 | NEW | AllplanAttributes - Bezeichnung: Fliesen Mosaik; Raumnr. Bauherr: 2.11_A2_02; ash B_Aufbau: B11; ash B_Rutschhemmung: R10; ash B_Bewertungsgruppe Barfußbereich: B
Gipsfaserplatten 2-lagig (BSK) | WUN-H2-E02-020a | CEILING | layer 0.036 m | 1216Dfl0000046333/01 | m² | Trockenbauarbeiten | 1 | 0.036 | 0 | 1 | Deckenfläche |  | 0 | 0 | NEW | 3.15 | AllplanAttributes - Bezeichnung: Gipsfaserplatten 2-lagig (BSK); ash_lichte Raumhöhe: 5.55917
 | WUN-H2-E02-020a | CEILING | B 0.1 m | 1216Dfl0813300408/01 | m² | Trockenbauarbeiten | 1 | 0.1 | 0 | 1 | Bekleidung | B | 0 | 0 | NEW | 2.5 | AllplanAttributes - ash_lichte Raumhöhe: 2.5; OKFF: 0; Pset_CoveringCommon - AcousticRating: -
 | WUN-H2-E02-020a | CEILING | D1 0.001 m | 1216Dfl0813300408/02 | m² | Maler- und Lackierarbeiten | 2 | 0.001 | 0 | 1 | Bekleidung | D1 | 0 | 0 | NEW | AllplanAttributes - OKFF: 0
PVC Bahnenware Holzoptik | WUN-H2-E02-082 | FLOORING | Ku1 0.15 m | 1216Bfl0000047476/01 | m² | Bodenbelagsarbeiten | 1 | 0.15 | 0 | 1 | Bodenfläche | Ku1 | 0 | 0 | NEW | AllplanAttributes - Bezeichnung: PVC Bahnenware Holzoptik; Raumnr. Bauherr: 2.11_A2_02; ash B_Aufbau: B9; ash B_Rutschhemmung: R9
Gipsfaserplatten 2-lagig (BSK) | WUN-H2-E02-082 | CEILING | layer 0.036 m | 1216Dfl0813270895/01 | m² | Trockenbauarbeiten | 1 | 0.036 | 0 | 1 | Deckenfläche |  | 0 | 0 | NEW | 3.15 | AllplanAttributes - Bezeichnung: Gipsfaserplatten 2-lagig (BSK); ash_lichte Raumhöhe: 4.40205
 | WUN-H2-E02-082 | CEILING | Aa 0.1 m | 1216Dfl0812858621/01 | m² | Trockenbauarbeiten | 1 | 0.1 | 0 | 1 | Bekleidung | Aa | 0 | 0 | NEW | 2.5 | AllplanAttributes - ash_lichte Raumhöhe: 2.5; OKFF: 0; Pset_CoveringCommon - AcousticRating: -
 | WUN-H2-E02-082 | CEILING | D1 0.001 m | 1216Dfl0812858621/02 | m² | Maler- und Lackierarbeiten | 2 | 0.001 | 0 | 1 | Bekleidung | D1 | 0 | 0 | NEW | AllplanAttributes - OKFF: 0
 | WUN-H2-E02-082 | CEILING | A1 0.1 m | 1216Dfl0000047488/01 | m² | Trockenbauarbeiten | 1 | 0.1 | 0 | 1 | Bekleidung | A1 | 0 | 0 | NEW | 2.5 | AllplanAttributes - ash_lichte Raumhöhe: 2.5; OKFF: 0; Pset_CoveringCommon - AcousticRating: -
 | WUN-H2-E02-082 | CEILING | D1 0.001 m | 1216Dfl0000047488/02 | m² | Maler- und Lackierarbeiten | 2 | 0.001 | 0 | 1 | Bekleidung | D1 | 0 | 0 | NEW | AllplanAttributes - OKFF: 0
PVC Bahnenware Holzoptik | WUN-H2-E02-085 | FLOORING | Ku1 0.15 m | 1216Bfl0000047448/01 | m² | Bodenbelagsarbeiten | 1 | 0.15 | 0 | 1 | Bodenfläche | Ku1 | 0 | 0 | NEW | AllplanAttributes - Bezeichnung: PVC Bahnenware Holzoptik; Raumnr. Bauherr: 2.11_A2_02; ash B_Aufbau: B9; ash B_Rutschhemmung: R9
Gipsfaserplatten 2-lagig (BSK) | WUN-H2-E02-085 | CEILING | layer 0.036 m | 1216Dfl0813270899/01 | m² | Trockenbauarbeiten | 1 | 0.036 | 0 | 1 | Deckenfläche |  | 0 | 0 | NEW | 3.15 | AllplanAttributes - Bezeichnung: Gipsfaserplatten 2-lagig (BSK); ash_lichte Raumhöhe: 4.40747
 | WUN-H2-E02-085 | CEILING | A1 0.1 m | 1216Dfl0000047460/01 | m² | Trockenbauarbeiten | 1 | 0.1 | 0 | 1 | Bekleidung | A1 | 0 | 0 | NEW | 2.5 | AllplanAttributes - ash_lichte Raumhöhe: 2.5; OKFF: 0; Pset_CoveringCommon - AcousticRating: -
 | WUN-H2-E02-085 | CEILING | D1 0.001 m | 1216Dfl0000047460/02 | m² | Maler- und Lackierarbeiten | 2 | 0.001 | 0 | 1 | Bekleidung | D1 | 0 | 0 | NEW | AllplanAttributes - OKFF: 0
 | WUN-H2-E02-085 | CEILING | Aa 0.1 m | 1216Dfl0812856881/01 | m² | Trockenbauarbeiten | 1 | 0.1 | 0 | 1 | Bekleidung | Aa | 0 | 0 | NEW | 2.5 | AllplanAttributes - ash_lichte Raumhöhe: 2.5; OKFF: 0; Pset_CoveringCommon - AcousticRating: -
 | WUN-H2-E02-085 | CEILING | D1 0.001 m | 1216Dfl0812856881/02 | m² | Maler- und Lackierarbeiten | 2 | 0.001 | 0 | 1 | Bekleidung | D1 | 0 | 0 | NEW | AllplanAttributes - OKFF: 0
PVC Bahnenware Holzoptik | WUN-H2-E02-084 | FLOORING | Ku1 0.15 m | 1216Bfl0000047624/01 | m² | Bodenbelagsarbeiten | 1 | 0.15 | 0 | 1 | Bodenfläche | Ku1 | 0 | 0 | NEW | AllplanAttributes - Bezeichnung: PVC Bahnenware Holzoptik; Raumnr. Bauherr: 2.11_A2_02; ash B_Aufbau: B9; ash B_Rutschhemmung: R9
Gipsfaserplatten 2-lagig (BSK) | WUN-H2-E02-084 | CEILING | layer 0.036 m | 1216Dfl0813270898/01 | m² | Trockenbauarbeiten | 1 | 0.036 | 0 | 1 | Deckenfläche |  | 0 | 0 | NEW | 3.15 | AllplanAttributes - Bezeichnung: Gipsfaserplatten 2-lagig (BSK); ash_lichte Raumhöhe: 4.41294
 | WUN-H2-E02-084 | CEILING | A1 0.1 m | 1216Dfl0000047636/01 | m² | Trockenbauarbeiten | 1 | 0.1 | 0 | 1 | Bekleidung | A1 | 0 | 0 | NEW | 2.5 | AllplanAttributes - ash_lichte Raumhöhe: 2.5; OKFF: 0; Pset_CoveringCommon - AcousticRating: -
 | WUN-H2-E02-084 | CEILING | D1 0.001 m | 1216Dfl0000047636/02 | m² | Maler- und Lackierarbeiten | 2 | 0.001 | 0 | 1 | Bekleidung | D1 | 0 | 0 | NEW | AllplanAttributes - OKFF: 0
 | WUN-H2-E02-084 | CEILING | Aa 0.1 m | 1216Dfl0812857461/01 | m² | Trockenbauarbeiten | 1 | 0.1 | 0 | 1 | Bekleidung | Aa | 0 | 0 | NEW | 2.5 | AllplanAttributes - ash_lichte Raumhöhe: 2.5; OKFF: 0; Pset_CoveringCommon - AcousticRating: -
 | WUN-H2-E02-084 | CEILING | D1 0.001 m | 1216Dfl0812857461/02 | m² | Maler- und Lackierarbeiten | 2 | 0.001 | 0 | 1 | Bekleidung | D1 | 0 | 0 | NEW | AllplanAttributes - OKFF: 0
PVC Bahnenware Holzoptik | WUN-H2-E02-086 | FLOORING | Ku1 0.15 m | 1216Bfl0000047434/01 | m² | Bodenbelagsarbeiten | 1 | 0.15 | 0 | 1 | Bodenfläche | Ku1 | 0 | 0 | NEW | AllplanAttributes - Bezeichnung: PVC Bahnenware Holzoptik; Raumnr. Bauherr: 2.11_A2_02; ash B_Aufbau: B9; ash B_Rutschhemmung: R9
Gipsfaserplatten 2-lagig (BSK) | WUN-H2-E02-086 | CEILING | layer 0.036 m | 1216Dfl0813270897/01 | m² | Trockenbauarbeiten | 1 | 0.036 | 0 | 1 | Deckenfläche |  | 0 | 0 | NEW | 3.15 | AllplanAttributes - Bezeichnung: Gipsfaserplatten 2-lagig (BSK); ash_lichte Raumhöhe: 4.4075
 | WUN-H2-E02-086 | CEILING | Aa 0.1 m | 1216Dfl0812856301/01 | m² | Trockenbauarbeiten | 1 | 0.1 | 0 | 1 | Bekleidung | Aa | 0 | 0 | NEW | 2.5 | AllplanAttributes - ash_lichte Raumhöhe: 2.5; OKFF: 0; Pset_CoveringCommon - AcousticRating: -
 | WUN-H2-E02-086 | CEILING | D1 0.001 m | 1216Dfl0812856301/02 | m² | Maler- und Lackierarbeiten | 2 | 0.001 | 0 | 1 | Bekleidung | D1 | 0 | 0 | NEW | AllplanAttributes - OKFF: 0
 | WUN-H2-E02-086 | CEILING | A1 0.1 m | 1216Dfl0000047446/01 | m² | Trockenbauarbeiten | 1 | 0.1 | 0 | 1 | Bekleidung | A1 | 0 | 0 | NEW | 2.5 | AllplanAttributes - ash_lichte Raumhöhe: 2.5; OKFF: 0; Pset_CoveringCommon - AcousticRating: -
 | WUN-H2-E02-086 | CEILING | D1 0.001 m | 1216Dfl0000047446/02 | m² | Maler- und Lackierarbeiten | 2 | 0.001 | 0 | 1 | Bekleidung | D1 | 0 | 0 | NEW | AllplanAttributes - OKFF: 0
PVC Bahnenware Holzoptik | WUN-H2-E02-083 | FLOORING | Ku1 0.15 m | 1216Bfl0000047462/01 | m² | Bodenbelagsarbeiten | 1 | 0.15 | 0 | 1 | Bodenfläche | Ku1 | 0 | 0 | NEW | AllplanAttributes - Bezeichnung: PVC Bahnenware Holzoptik; Raumnr. Bauherr: 2.11_A2_02; ash B_Aufbau: B9; ash B_Rutschhemmung: R9
Gipsfaserplatten 2-lagig (BSK) | WUN-H2-E02-083 | CEILING | layer 0.036 m | 1216Dfl0813270896/01 | m² | Trockenbauarbeiten | 1 | 0.036 | 0 | 1 | Deckenfläche |  | 0 | 0 | NEW | 3.15 | AllplanAttributes - Bezeichnung: Gipsfaserplatten 2-lagig (BSK); ash_lichte Raumhöhe: 4.40747
 | WUN-H2-E02-083 | CEILING | A1 0.1 m | 1216Dfl0000047474/01 | m² | Trockenbauarbeiten | 1 | 0.1 | 0 | 1 | Bekleidung | A1 | 0 | 0 | NEW | 2.5 | AllplanAttributes - ash_lichte Raumhöhe: 2.5; OKFF: 0; Pset_CoveringCommon - AcousticRating: -
 | WUN-H2-E02-083 | CEILING | D1 0.001 m | 1216Dfl0000047474/02 | m² | Maler- und Lackierarbeiten | 2 | 0.001 | 0 | 1 | Bekleidung | D1 | 0 | 0 | NEW | AllplanAttributes - OKFF: 0
 | WUN-H2-E02-083 | CEILING | Aa 0.1 m | 1216Dfl0812858041/01 | m² | Trockenbauarbeiten | 1 | 0.1 | 0 | 1 | Bekleidung | Aa | 0 | 0 | NEW | 2.5 | AllplanAttributes - ash_lichte Raumhöhe: 2.5; OKFF: 0; Pset_CoveringCommon - AcousticRating: -
 | WUN-H2-E02-083 | CEILING | D1 0.001 m | 1216Dfl0812858041/02 | m² | Maler- und Lackierarbeiten | 2 | 0.001 | 0 | 1 | Bekleidung | D1 | 0 | 0 | NEW | AllplanAttributes - OKFF: 0
PVC Bahnenware Holzoptik | WUN-H2-E02-068 | FLOORING | Ku1 0.15 m | 1216Bfl0000047264/01 | m² | Bodenbelagsarbeiten | 1 | 0.15 | 0 | 1 | Bodenfläche | Ku1 | 0 | 0 | NEW | AllplanAttributes - Bezeichnung: PVC Bahnenware Holzoptik; Raumnr. Bauherr: 2.11_A2_02; ash B_Aufbau: B9; ash B_Rutschhemmung: R9
Acrovyn | WUN-H2-E02-068 | CLADDING | 84 0.001 m | 1216Sfl0812840513/02 | m² | Maler- und Lackierarbeiten | 2 | 0.001 | 0 | 1 | Seitenfläche | 84 | 0 | 0 | NEW | AllplanAttributes - Bezeichnung: Acrovyn
Gipsfaserplatten 2-lagig (BSK) | WUN-H2-E02-068 | CEILING | layer 0.036 m | 1216Dfl0000047265/01 | m² | Trockenbauarbeiten | 1 | 0.036 | 0 | 1 | Deckenfläche |  | 0 | 0 | NEW | 3.15 | AllplanAttributes - Bezeichnung: Gipsfaserplatten 2-lagig (BSK); ash_lichte Raumhöhe: 4.82692
 | WUN-H2-E02-068 | CEILING | A1 0.1 m | 1216Dfl0000047276/01 | m² | Trockenbauarbeiten | 1 | 0.1 | 0 | 1 | Bekleidung | A1 | 0 | 0 | NEW | 2.5 | AllplanAttributes - ash_lichte Raumhöhe: 2.5; OKFF: 0; Pset_CoveringCommon - AcousticRating: -
 | WUN-H2-E02-068 | CEILING | D1 0.001 m | 1216Dfl0000047276/02 | m² | Maler- und Lackierarbeiten | 2 | 0.001 | 0 | 1 | Bekleidung | D1 | 0 | 0 | NEW | AllplanAttributes - OKFF: 0
 | WUN-H2-E02-068 | CEILING | A1 0.1 m | 1216Dfl0813265951/01 | m² | Trockenbauarbeiten | 1 | 0.1 | 0 | 1 | Bekleidung | A1 | 0 | 0 | NEW | 2.5 | AllplanAttributes - ash_lichte Raumhöhe: 3.150000; OKFF: 0; Pset_CoveringCommon - AcousticRating: -
 | WUN-H2-E02-068 | CEILING | D1 0.001 m | 1216Dfl0813265951/02 | m² | Maler- und Lackierarbeiten | 2 | 0.001 | 0 | 1 | Bekleidung | D1 | 0 | 0 | NEW | 2.5 | AllplanAttributes - ash_lichte Raumhöhe: 3.150000; OKFF: 0
PVC Bahnenware Holzoptik | WUN-H2-E02-074 | FLOORING | Ku1 0.15 m | 1216Bfl0000047408/01 | m² | Bodenbelagsarbeiten | 1 | 0.15 | 0 | 1 | Bodenfläche | Ku1 | 0 | 0 | NEW | AllplanAttributes - Bezeichnung: PVC Bahnenware Holzoptik; Raumnr. Bauherr: 2.11_A2_02; ash B_Aufbau: B9; ash B_Rutschhemmung: R9
Acrovyn | WUN-H2-E02-074 | CLADDING | 84 0.001 m | 1216Sfl0812842708/02 | m² | Maler- und Lackierarbeiten | 2 | 0.001 | 0 | 1 | Seitenfläche | 84 | 0 | 0 | NEW | AllplanAttributes - Bezeichnung: Acrovyn
Acrovyn | WUN-H2-E02-074 | CLADDING | 84 0.001 m | 1216Sfl0812842712/02 | m² | Maler- und Lackierarbeiten | 2 | 0.001 | 0 | 1 | Seitenfläche | 84 | 0 | 0 | NEW | AllplanAttributes - Bezeichnung: Acrovyn
Gipsfaserplatten 2-lagig (BSK) | WUN-H2-E02-074 | CEILING | layer 0.036 m | 1216Dfl0000047409/01 | m² | Trockenbauarbeiten | 1 | 0.036 | 0 | 1 | Deckenfläche |  | 0 | 0 | NEW | 3.15 | AllplanAttributes - Bezeichnung: Gipsfaserplatten 2-lagig (BSK); ash_lichte Raumhöhe: 3.47056
 | WUN-H2-E02-074 | CEILING | A1 0.1 m | 1216Dfl0000047420/01 | m² | Trockenbauarbeiten | 1 | 0.1 | 0 | 1 | Bekleidung | A1 | 0 | 0 | NEW | 2.5 | AllplanAttributes - ash_lichte Raumhöhe: 2.5; OKFF: 0; Pset_CoveringCommon - AcousticRating: -
 | WUN-H2-E02-074 | CEILING | D1 0.001 m | 1216Dfl0000047420/02 | m² | Maler- und Lackierarbeiten | 2 | 0.001 | 0 | 1 | Bekleidung | D1 | 0 | 0 | NEW | AllplanAttributes - OKFF: 0
 | WUN-H2-E02-074 | CEILING | A1 0.1 m | 1216Dfl0813268303/01 | m² | Trockenbauarbeiten | 1 | 0.1 | 0 | 1 | Bekleidung | A1 | 0 | 0 | NEW | 2.5 | AllplanAttributes - ash_lichte Raumhöhe: 3.150000; OKFF: 0; Pset_CoveringCommon - AcousticRating: -
 | WUN-H2-E02-074 | CEILING | D1 0.001 m | 1216Dfl0813268303/02 | m² | Maler- und Lackierarbeiten | 2 | 0.001 | 0 | 1 | Bekleidung | D1 | 0 | 0 | NEW | 2.5 | AllplanAttributes - ash_lichte Raumhöhe: 3.150000; OKFF: 0
PVC Bahnenware Holzoptik | WUN-H2-E02-073 | FLOORING | Ku1 0.15 m | 1216Bfl0000047382/01 | m² | Bodenbelagsarbeiten | 1 | 0.15 | 0 | 1 | Bodenfläche | Ku1 | 0 | 0 | NEW | AllplanAttributes - Bezeichnung: PVC Bahnenware Holzoptik; Raumnr. Bauherr: 2.11_A2_02; ash B_Aufbau: B9; ash B_Rutschhemmung: R9
Acrovyn | WUN-H2-E02-073 | CLADDING | 84 0.001 m | 1216Sfl0812842710/02 | m² | Maler- und Lackierarbeiten | 2 | 0.001 | 0 | 1 | Seitenfläche | 84 | 0 | 0 | NEW | AllplanAttributes - Bezeichnung: Acrovyn
Acrovyn | WUN-H2-E02-073 | CLADDING | 84 0.001 m | 1216Sfl0812842702/02 | m² | Maler- und Lackierarbeiten | 2 | 0.001 | 0 | 1 | Seitenfläche | 84 | 0 | 0 | NEW | AllplanAttributes - Bezeichnung: Acrovyn
Gipsfaserplatten 2-lagig (BSK) | WUN-H2-E02-073 | CEILING | layer 0.036 m | 1216Dfl0000047383/01 | m² | Trockenbauarbeiten | 1 | 0.036 | 0 | 1 | Deckenfläche |  | 0 | 0 | NEW | 3.15 | AllplanAttributes - Bezeichnung: Gipsfaserplatten 2-lagig (BSK); ash_lichte Raumhöhe: 3.95778
 | WUN-H2-E02-073 | CEILING | A1 0.1 m | 1216Dfl0000047394/01 | m² | Trockenbauarbeiten | 1 | 0.1 | 0 | 1 | Bekleidung | A1 | 0 | 0 | NEW | 2.5 | AllplanAttributes - ash_lichte Raumhöhe: 2.5; OKFF: 0; Pset_CoveringCommon - AcousticRating: -
 | WUN-H2-E02-073 | CEILING | D1 0.001 m | 1216Dfl0000047394/02 | m² | Maler- und Lackierarbeiten | 2 | 0.001 | 0 | 1 | Bekleidung | D1 | 0 | 0 | NEW | AllplanAttributes - OKFF: 0
 | WUN-H2-E02-073 | CEILING | A1 0.1 m | 1216Dfl0813267911/01 | m² | Trockenbauarbeiten | 1 | 0.1 | 0 | 1 | Bekleidung | A1 | 0 | 0 | NEW | 2.5 | AllplanAttributes - ash_lichte Raumhöhe: 3.150000; OKFF: 0; Pset_CoveringCommon - AcousticRating: -
 | WUN-H2-E02-073 | CEILING | D1 0.001 m | 1216Dfl0813267911/02 | m² | Maler- und Lackierarbeiten | 2 | 0.001 | 0 | 1 | Bekleidung | D1 | 0 | 0 | NEW | 2.5 | AllplanAttributes - ash_lichte Raumhöhe: 3.150000; OKFF: 0
PVC Bahnenware Holzoptik | WUN-H2-E02-070 | FLOORING | Ku1 0.15 m | 1216Bfl0000047304/01 | m² | Bodenbelagsarbeiten | 1 | 0.15 | 0 | 1 | Bodenfläche | Ku1 | 0 | 0 | NEW | AllplanAttributes - Bezeichnung: PVC Bahnenware Holzoptik; Raumnr. Bauherr: 2.11_A2_02; ash B_Aufbau: B9; ash B_Rutschhemmung: R9
Acrovyn | WUN-H2-E02-070 | CLADDING | 84 0.001 m | 1216Sfl0812842698/02 | m² | Maler- und Lackierarbeiten | 2 | 0.001 | 0 | 1 | Seitenfläche | 84 | 0 | 0 | NEW | AllplanAttributes - Bezeichnung: Acrovyn
Acrovyn | WUN-H2-E02-070 | CLADDING | 84 0.001 m | 1216Sfl0812842716/02 | m² | Maler- und Lackierarbeiten | 2 | 0.001 | 0 | 1 | Seitenfläche | 84 | 0 | 0 | NEW | AllplanAttributes - Bezeichnung: Acrovyn
Gipsfaserplatten 2-lagig (BSK) | WUN-H2-E02-070 | CEILING | layer 0.036 m | 1216Dfl0000047305/01 | m² | Trockenbauarbeiten | 1 | 0.036 | 0 | 1 | Deckenfläche |  | 0 | 0 | NEW | 3.15 | AllplanAttributes - Bezeichnung: Gipsfaserplatten 2-lagig (BSK); ash_lichte Raumhöhe: 5.21787
 | WUN-H2-E02-070 | CEILING | A1 0.1 m | 1216Dfl0000047316/01 | m² | Trockenbauarbeiten | 1 | 0.1 | 0 | 1 | Bekleidung | A1 | 0 | 0 | NEW | 2.5 | AllplanAttributes - ash_lichte Raumhöhe: 2.5; OKFF: 0; Pset_CoveringCommon - AcousticRating: -
 | WUN-H2-E02-070 | CEILING | D1 0.001 m | 1216Dfl0000047316/02 | m² | Maler- und Lackierarbeiten | 2 | 0.001 | 0 | 1 | Bekleidung | D1 | 0 | 0 | NEW | AllplanAttributes - OKFF: 0
 | WUN-H2-E02-070 | CEILING | A1 0.1 m | 1216Dfl0813266735/01 | m² | Trockenbauarbeiten | 1 | 0.1 | 0 | 1 | Bekleidung | A1 | 0 | 0 | NEW | 2.5 | AllplanAttributes - ash_lichte Raumhöhe: 3.150000; OKFF: 0; Pset_CoveringCommon - AcousticRating: -
 | WUN-H2-E02-070 | CEILING | D1 0.001 m | 1216Dfl0813266735/02 | m² | Maler- und Lackierarbeiten | 2 | 0.001 | 0 | 1 | Bekleidung | D1 | 0 | 0 | NEW | 2.5 | AllplanAttributes - ash_lichte Raumhöhe: 3.150000; OKFF: 0
PVC Bahnenware Holzoptik | WUN-H2-E02-072 | FLOORING | Ku1 0.15 m | 1216Bfl0000047356/01 | m² | Bodenbelagsarbeiten | 1 | 0.15 | 0 | 1 | Bodenfläche | Ku1 | 0 | 0 | NEW | AllplanAttributes - Bezeichnung: PVC Bahnenware Holzoptik; Raumnr. Bauherr: 2.11_A2_02; ash B_Aufbau: B9; ash B_Rutschhemmung: R9
Acrovyn | WUN-H2-E02-072 | CLADDING | 84 0.001 m | 1216Sfl0812842700/02 | m² | Maler- und Lackierarbeiten | 2 | 0.001 | 0 | 1 | Seitenfläche | 84 | 0 | 0 | NEW | AllplanAttributes - Bezeichnung: Acrovyn
Acrovyn | WUN-H2-E02-072 | CLADDING | 84 0.001 m | 1216Sfl0812842704/02 | m² | Maler- und Lackierarbeiten | 2 | 0.001 | 0 | 1 | Seitenfläche | 84 | 0 | 0 | NEW | AllplanAttributes - Bezeichnung: Acrovyn
Gipsfaserplatten 2-lagig (BSK) | WUN-H2-E02-072 | CEILING | layer 0.036 m | 1216Dfl0000047357/01 | m² | Trockenbauarbeiten | 1 | 0.036 | 0 | 1 | Deckenfläche |  | 0 | 0 | NEW | 3.15 | AllplanAttributes - Bezeichnung: Gipsfaserplatten 2-lagig (BSK); ash_lichte Raumhöhe: 4.3691
 | WUN-H2-E02-072 | CEILING | A1 0.1 m | 1216Dfl0000047368/01 | m² | Trockenbauarbeiten | 1 | 0.1 | 0 | 1 | Bekleidung | A1 | 0 | 0 | NEW | 2.5 | AllplanAttributes - ash_lichte Raumhöhe: 2.5; OKFF: 0; Pset_CoveringCommon - AcousticRating: -
 | WUN-H2-E02-072 | CEILING | D1 0.001 m | 1216Dfl0000047368/02 | m² | Maler- und Lackierarbeiten | 2 | 0.001 | 0 | 1 | Bekleidung | D1 | 0 | 0 | NEW | AllplanAttributes - OKFF: 0
 | WUN-H2-E02-072 | CEILING | A1 0.1 m | 1216Dfl0813267519/01 | m² | Trockenbauarbeiten | 1 | 0.1 | 0 | 1 | Bekleidung | A1 | 0 | 0 | NEW | 2.5 | AllplanAttributes - ash_lichte Raumhöhe: 3.150000; OKFF: 0; Pset_CoveringCommon - AcousticRating: -
 | WUN-H2-E02-072 | CEILING | D1 0.001 m | 1216Dfl0813267519/02 | m² | Maler- und Lackierarbeiten | 2 | 0.001 | 0 | 1 | Bekleidung | D1 | 0 | 0 | NEW | 2.5 | AllplanAttributes - ash_lichte Raumhöhe: 3.150000; OKFF: 0
PVC Bahnenware Holzoptik | WUN-H2-E02-071 | FLOORING | Ku1 0.15 m | 1216Bfl0000047330/01 | m² | Bodenbelagsarbeiten | 1 | 0.15 | 0 | 1 | Bodenfläche | Ku1 | 0 | 0 | NEW | AllplanAttributes - Bezeichnung: PVC Bahnenware Holzoptik; Raumnr. Bauherr: 2.11_A2_02; ash B_Aufbau: B9; ash B_Rutschhemmung: R9
Acrovyn | WUN-H2-E02-071 | CLADDING | 84 0.001 m | 1216Sfl0812842714/02 | m² | Maler- und Lackierarbeiten | 2 | 0.001 | 0 | 1 | Seitenfläche | 84 | 0 | 0 | NEW | AllplanAttributes - Bezeichnung: Acrovyn
Gipsfaserplatten 2-lagig (BSK) | WUN-H2-E02-071 | CEILING | layer 0.036 m | 1216Dfl0000047331/01 | m² | Trockenbauarbeiten | 1 | 0.036 | 0 | 1 | Deckenfläche |  | 0 | 0 | NEW | 3.15 | AllplanAttributes - Bezeichnung: Gipsfaserplatten 2-lagig (BSK); ash_lichte Raumhöhe: 4.86395
 | WUN-H2-E02-071 | CEILING | A1 0.1 m | 1216Dfl0000047342/01 | m² | Trockenbauarbeiten | 1 | 0.1 | 0 | 1 | Bekleidung | A1 | 0 | 0 | NEW | 2.5 | AllplanAttributes - ash_lichte Raumhöhe: 2.5; OKFF: 0; Pset_CoveringCommon - AcousticRating: -
 | WUN-H2-E02-071 | CEILING | D1 0.001 m | 1216Dfl0000047342/02 | m² | Maler- und Lackierarbeiten | 2 | 0.001 | 0 | 1 | Bekleidung | D1 | 0 | 0 | NEW | AllplanAttributes - OKFF: 0
 | WUN-H2-E02-071 | CEILING | A1 0.1 m | 1216Dfl0813267127/01 | m² | Trockenbauarbeiten | 1 | 0.1 | 0 | 1 | Bekleidung | A1 | 0 | 0 | NEW | 2.5 | AllplanAttributes - ash_lichte Raumhöhe: 3.150000; OKFF: 0; Pset_CoveringCommon - AcousticRating: -
 | WUN-H2-E02-071 | CEILING | D1 0.001 m | 1216Dfl0813267127/02 | m² | Maler- und Lackierarbeiten | 2 | 0.001 | 0 | 1 | Bekleidung | D1 | 0 | 0 | NEW | 2.5 | AllplanAttributes - ash_lichte Raumhöhe: 3.150000; OKFF: 0
PVC Bahnenware Holzoptik | WUN-H2-E02-069 | FLOORING | Ku1 0.15 m | 1216Bfl0000047278/01 | m² | Bodenbelagsarbeiten | 1 | 0.15 | 0 | 1 | Bodenfläche | Ku1 | 0 | 0 | NEW | AllplanAttributes - Bezeichnung: PVC Bahnenware Holzoptik; Raumnr. Bauherr: 2.11_A2_02; ash B_Aufbau: B9; ash B_Rutschhemmung: R9
Acrovyn | WUN-H2-E02-069 | CLADDING | 84 0.001 m | 1216Sfl0812842696/02 | m² | Maler- und Lackierarbeiten | 2 | 0.001 | 0 | 1 | Seitenfläche | 84 | 0 | 0 | NEW | AllplanAttributes - Bezeichnung: Acrovyn
Acrovyn | WUN-H2-E02-069 | CLADDING | 84 0.001 m | 1216Sfl0812842718/02 | m² | Maler- und Lackierarbeiten | 2 | 0.001 | 0 | 1 | Seitenfläche | 84 | 0 | 0 | NEW | AllplanAttributes - Bezeichnung: Acrovyn
Gipsfaserplatten 2-lagig (BSK) | WUN-H2-E02-069 | CEILING | layer 0.036 m | 1216Dfl0000047279/01 | m² | Trockenbauarbeiten | 1 | 0.036 | 0 | 1 | Deckenfläche |  | 0 | 0 | NEW | 3.15 | AllplanAttributes - Bezeichnung: Gipsfaserplatten 2-lagig (BSK); ash_lichte Raumhöhe: 5.7076
 | WUN-H2-E02-069 | CEILING | A1 0.1 m | 1216Dfl0000047290/01 | m² | Trockenbauarbeiten | 1 | 0.1 | 0 | 1 | Bekleidung | A1 | 0 | 0 | NEW | 2.5 | AllplanAttributes - ash_lichte Raumhöhe: 2.5; OKFF: 0; Pset_CoveringCommon - AcousticRating: -
 | WUN-H2-E02-069 | CEILING | D1 0.001 m | 1216Dfl0000047290/02 | m² | Maler- und Lackierarbeiten | 2 | 0.001 | 0 | 1 | Bekleidung | D1 | 0 | 0 | NEW | AllplanAttributes - OKFF: 0
 | WUN-H2-E02-069 | CEILING | A1 0.1 m | 1216Dfl0813266343/01 | m² | Trockenbauarbeiten | 1 | 0.1 | 0 | 1 | Bekleidung | A1 | 0 | 0 | NEW | 2.5 | AllplanAttributes - ash_lichte Raumhöhe: 3.150000; OKFF: 0; Pset_CoveringCommon - AcousticRating: -
 | WUN-H2-E02-069 | CEILING | D1 0.001 m | 1216Dfl0813266343/02 | m² | Maler- und Lackierarbeiten | 2 | 0.001 | 0 | 1 | Bekleidung | D1 | 0 | 0 | NEW | 2.5 | AllplanAttributes - ash_lichte Raumhöhe: 3.150000; OKFF: 0
Fliesen | WUN-H2-E02-068a | FLOORING | Fl1 0.15 m | 1216Bfl0000047252/01 | m² | Bodenbelagsarbeiten | 1 | 0.15 | 0 | 1 | Bodenfläche | Fl1 | 0 | 0 | NEW | AllplanAttributes - Bezeichnung: Fliesen; Raumnr. Bauherr: 2.11_A2_02; ash B_Aufbau: B10; ash B_Rutschhemmung: R10
Fliesen Mosaik | WUN-H2-E02-068a | FLOORING | Fl2 0.15 m | 1216Bfl0813119865/01 | m² | Bodenbelagsarbeiten | 1 | 0.15 | 0 | 1 | Bodenfläche | Fl2 | 0 | 0 | NEW | AllplanAttributes - Bezeichnung: Fliesen Mosaik; Raumnr. Bauherr: 2.11_A2_02; ash B_Aufbau: B11; ash B_Rutschhemmung: R10; ash B_Bewertungsgruppe Barfußbereich: B
Gipsfaserplatten 2-lagig (BSK) | WUN-H2-E02-068a | CEILING | layer 0.036 m | 1216Dfl0000047253/01 | m² | Trockenbauarbeiten | 1 | 0.036 | 0 | 1 | Deckenfläche |  | 0 | 0 | NEW | 3.15 | AllplanAttributes - Bezeichnung: Gipsfaserplatten 2-lagig (BSK); ash_lichte Raumhöhe: 4.55685
 | WUN-H2-E02-068a | CEILING | B 0.1 m | 1216Dfl0813265559/01 | m² | Trockenbauarbeiten | 1 | 0.1 | 0 | 1 | Bekleidung | B | 0 | 0 | NEW | 2.5 | AllplanAttributes - ash_lichte Raumhöhe: 2.5; OKFF: 0; Pset_CoveringCommon - AcousticRating: -
 | WUN-H2-E02-068a | CEILING | D1 0.001 m | 1216Dfl0813265559/02 | m² | Maler- und Lackierarbeiten | 2 | 0.001 | 0 | 1 | Bekleidung | D1 | 0 | 0 | NEW | AllplanAttributes - OKFF: 0
Fliesen | WUN-H2-E02-069a | FLOORING | Fl1 0.15 m | 1216Bfl0000047292/01 | m² | Bodenbelagsarbeiten | 1 | 0.15 | 0 | 1 | Bodenfläche | Fl1 | 0 | 0 | NEW | AllplanAttributes - Bezeichnung: Fliesen; Raumnr. Bauherr: 2.11_A2_02; ash B_Aufbau: B10; ash B_Rutschhemmung: R10
Fliesen Mosaik | WUN-H2-E02-069a | FLOORING | Fl2 0.15 m | 1216Bfl0813119665/01 | m² | Bodenbelagsarbeiten | 1 | 0.15 | 0 | 1 | Bodenfläche | Fl2 | 0 | 0 | NEW | AllplanAttributes - Bezeichnung: Fliesen Mosaik; Raumnr. Bauherr: 2.11_A2_02; ash B_Aufbau: B11; ash B_Rutschhemmung: R10; ash B_Bewertungsgruppe Barfußbereich: B
Gipsfaserplatten 2-lagig (BSK) | WUN-H2-E02-069a | CEILING | layer 0.036 m | 1216Dfl0000047293/01 | m² | Trockenbauarbeiten | 1 | 0.036 | 0 | 1 | Deckenfläche |  | 0 | 0 | NEW | 3.15 | AllplanAttributes - Bezeichnung: Gipsfaserplatten 2-lagig (BSK); ash_lichte Raumhöhe: 5.55698
 | WUN-H2-E02-069a | CEILING | B 0.1 m | 1216Dfl0813265167/01 | m² | Trockenbauarbeiten | 1 | 0.1 | 0 | 1 | Bekleidung | B | 0 | 0 | NEW | 2.5 | AllplanAttributes - ash_lichte Raumhöhe: 2.5; OKFF: 0; Pset_CoveringCommon - AcousticRating: -
 | WUN-H2-E02-069a | CEILING | D1 0.001 m | 1216Dfl0813265167/02 | m² | Maler- und Lackierarbeiten | 2 | 0.001 | 0 | 1 | Bekleidung | D1 | 0 | 0 | NEW | AllplanAttributes - OKFF: 0
Fliesen | WUN-H2-E02-070a | FLOORING | Fl1 0.15 m | 1216Bfl0000047318/01 | m² | Bodenbelagsarbeiten | 1 | 0.15 | 0 | 1 | Bodenfläche | Fl1 | 0 | 0 | NEW | AllplanAttributes - Bezeichnung: Fliesen; Raumnr. Bauherr: 2.11_A2_02; ash B_Aufbau: B10; ash B_Rutschhemmung: R10
Fliesen Mosaik | WUN-H2-E02-070a | FLOORING | Fl2 0.15 m | 1216Bfl0813119465/01 | m² | Bodenbelagsarbeiten | 1 | 0.15 | 0 | 1 | Bodenfläche | Fl2 | 0 | 0 | NEW | AllplanAttributes - Bezeichnung: Fliesen Mosaik; Raumnr. Bauherr: 2.11_A2_02; ash B_Aufbau: B11; ash B_Rutschhemmung: R10; ash B_Bewertungsgruppe Barfußbereich: B
Gipsfaserplatten 2-lagig (BSK) | WUN-H2-E02-070a | CEILING | layer 0.036 m | 1216Dfl0000047319/01 | m² | Trockenbauarbeiten | 1 | 0.036 | 0 | 1 | Deckenfläche |  | 0 | 0 | NEW | 3.15 | AllplanAttributes - Bezeichnung: Gipsfaserplatten 2-lagig (BSK); ash_lichte Raumhöhe: 5.36446
 | WUN-H2-E02-070a | CEILING | B 0.1 m | 1216Dfl0813264775/01 | m² | Trockenbauarbeiten | 1 | 0.1 | 0 | 1 | Bekleidung | B | 0 | 0 | NEW | 2.5 | AllplanAttributes - ash_lichte Raumhöhe: 2.5; OKFF: 0; Pset_CoveringCommon - AcousticRating: -
 | WUN-H2-E02-070a | CEILING | D1 0.001 m | 1216Dfl0813264775/02 | m² | Maler- und Lackierarbeiten | 2 | 0.001 | 0 | 1 | Bekleidung | D1 | 0 | 0 | NEW | AllplanAttributes - OKFF: 0
Fliesen | WUN-H2-E02-071a | FLOORING | Fl1 0.15 m | 1216Bfl0000047344/01 | m² | Bodenbelagsarbeiten | 1 | 0.15 | 0 | 1 | Bodenfläche | Fl1 | 0 | 0 | NEW | AllplanAttributes - Bezeichnung: Fliesen; Raumnr. Bauherr: 2.11_A2_02; ash B_Aufbau: B10; ash B_Rutschhemmung: R10
Fliesen Mosaik | WUN-H2-E02-071a | FLOORING | Fl2 0.15 m | 1216Bfl0813119265/01 | m² | Bodenbelagsarbeiten | 1 | 0.15 | 0 | 1 | Bodenfläche | Fl2 | 0 | 0 | NEW | AllplanAttributes - Bezeichnung: Fliesen Mosaik; Raumnr. Bauherr: 2.11_A2_02; ash B_Aufbau: B11; ash B_Rutschhemmung: R10; ash B_Bewertungsgruppe Barfußbereich: B
Gipsfaserplatten 2-lagig (BSK) | WUN-H2-E02-071a | CEILING | layer 0.036 m | 1216Dfl0000047345/01 | m² | Trockenbauarbeiten | 1 | 0.036 | 0 | 1 | Deckenfläche |  | 0 | 0 | NEW | 3.15 | AllplanAttributes - Bezeichnung: Gipsfaserplatten 2-lagig (BSK); ash_lichte Raumhöhe: 4.74972
 | WUN-H2-E02-071a | CEILING | B 0.1 m | 1216Dfl0813264383/01 | m² | Trockenbauarbeiten | 1 | 0.1 | 0 | 1 | Bekleidung | B | 0 | 0 | NEW | 2.5 | AllplanAttributes - ash_lichte Raumhöhe: 2.5; OKFF: 0; Pset_CoveringCommon - AcousticRating: -
 | WUN-H2-E02-071a | CEILING | D1 0.001 m | 1216Dfl0813264383/02 | m² | Maler- und Lackierarbeiten | 2 | 0.001 | 0 | 1 | Bekleidung | D1 | 0 | 0 | NEW | AllplanAttributes - OKFF: 0
Fliesen | WUN-H2-E02-072a | FLOORING | Fl1 0.15 m | 1216Bfl0000047370/01 | m² | Bodenbelagsarbeiten | 1 | 0.15 | 0 | 1 | Bodenfläche | Fl1 | 0 | 0 | NEW | AllplanAttributes - Bezeichnung: Fliesen; Raumnr. Bauherr: 2.11_A2_02; ash B_Aufbau: B10; ash B_Rutschhemmung: R10
Fliesen Mosaik | WUN-H2-E02-072a | FLOORING | Fl2 0.15 m | 1216Bfl0813119065/01 | m² | Bodenbelagsarbeiten | 1 | 0.15 | 0 | 1 | Bodenfläche | Fl2 | 0 | 0 | NEW | AllplanAttributes - Bezeichnung: Fliesen Mosaik; Raumnr. Bauherr: 2.11_A2_02; ash B_Aufbau: B11; ash B_Rutschhemmung: R10; ash B_Bewertungsgruppe Barfußbereich: B
Gipsfaserplatten 2-lagig (BSK) | WUN-H2-E02-072a | CEILING | layer 0.036 m | 1216Dfl0000047371/01 | m² | Trockenbauarbeiten | 1 | 0.036 | 0 | 1 | Deckenfläche |  | 0 | 0 | NEW | 3.15 | AllplanAttributes - Bezeichnung: Gipsfaserplatten 2-lagig (BSK); ash_lichte Raumhöhe: 4.51891
 | WUN-H2-E02-072a | CEILING | B 0.1 m | 1216Dfl0813263991/01 | m² | Trockenbauarbeiten | 1 | 0.1 | 0 | 1 | Bekleidung | B | 0 | 0 | NEW | 2.5 | AllplanAttributes - ash_lichte Raumhöhe: 2.5; OKFF: 0; Pset_CoveringCommon - AcousticRating: -
 | WUN-H2-E02-072a | CEILING | D1 0.001 m | 1216Dfl0813263991/02 | m² | Maler- und Lackierarbeiten | 2 | 0.001 | 0 | 1 | Bekleidung | D1 | 0 | 0 | NEW | AllplanAttributes - OKFF: 0
Fliesen | WUN-H2-E02-073a | FLOORING | Fl1 0.15 m | 1216Bfl0000047396/01 | m² | Bodenbelagsarbeiten | 1 | 0.15 | 0 | 1 | Bodenfläche | Fl1 | 0 | 0 | NEW | AllplanAttributes - Bezeichnung: Fliesen; Raumnr. Bauherr: 2.11_A2_02; ash B_Aufbau: B10; ash B_Rutschhemmung: R10
Fliesen Mosaik | WUN-H2-E02-073a | FLOORING | Fl2 0.15 m | 1216Bfl0813118865/01 | m² | Bodenbelagsarbeiten | 1 | 0.15 | 0 | 1 | Bodenfläche | Fl2 | 0 | 0 | NEW | AllplanAttributes - Bezeichnung: Fliesen Mosaik; Raumnr. Bauherr: 2.11_A2_02; ash B_Aufbau: B11; ash B_Rutschhemmung: R10; ash B_Bewertungsgruppe Barfußbereich: B
Gipsfaserplatten 2-lagig (BSK) | WUN-H2-E02-073a | CEILING | layer 0.036 m | 1216Dfl0000047397/01 | m² | Trockenbauarbeiten | 1 | 0.036 | 0 | 1 | Deckenfläche |  | 0 | 0 | NEW | 3.15 | AllplanAttributes - Bezeichnung: Gipsfaserplatten 2-lagig (BSK); ash_lichte Raumhöhe: 3.81119
 | WUN-H2-E02-073a | CEILING | B 0.1 m | 1216Dfl0813263599/01 | m² | Trockenbauarbeiten | 1 | 0.1 | 0 | 1 | Bekleidung | B | 0 | 0 | NEW | 2.5 | AllplanAttributes - ash_lichte Raumhöhe: 2.5; OKFF: 0; Pset_CoveringCommon - AcousticRating: -
 | WUN-H2-E02-073a | CEILING | D1 0.001 m | 1216Dfl0813263599/02 | m² | Maler- und Lackierarbeiten | 2 | 0.001 | 0 | 1 | Bekleidung | D1 | 0 | 0 | NEW | AllplanAttributes - OKFF: 0
Fliesen | WUN-H2-E02-074a | FLOORING | Fl1 0.15 m | 1216Bfl0000047422/01 | m² | Bodenbelagsarbeiten | 1 | 0.15 | 0 | 1 | Bodenfläche | Fl1 | 0 | 0 | NEW | AllplanAttributes - Bezeichnung: Fliesen; Raumnr. Bauherr: 2.11_A2_02; ash B_Aufbau: B10; ash B_Rutschhemmung: R10
Fliesen Mosaik | WUN-H2-E02-074a | FLOORING | Fl2 0.15 m | 1216Bfl0813118665/01 | m² | Bodenbelagsarbeiten | 1 | 0.15 | 0 | 1 | Bodenfläche | Fl2 | 0 | 0 | NEW | AllplanAttributes - Bezeichnung: Fliesen Mosaik; Raumnr. Bauherr: 2.11_A2_02; ash B_Aufbau: B11; ash B_Rutschhemmung: R10; ash B_Bewertungsgruppe Barfußbereich: B
Gipsfaserplatten 2-lagig (BSK) | WUN-H2-E02-074a | CEILING | layer 0.036 m | 1216Dfl0000047423/01 | m² | Trockenbauarbeiten | 1 | 0.036 | 0 | 1 | Deckenfläche |  | 0 | 0 | NEW | 3.15 | AllplanAttributes - Bezeichnung: Gipsfaserplatten 2-lagig (BSK); ash_lichte Raumhöhe: 3.61867
 | WUN-H2-E02-074a | CEILING | B 0.1 m | 1216Dfl0813263207/01 | m² | Trockenbauarbeiten | 1 | 0.1 | 0 | 1 | Bekleidung | B | 0 | 0 | NEW | 2.5 | AllplanAttributes - ash_lichte Raumhöhe: 2.5; OKFF: 0; Pset_CoveringCommon - AcousticRating: -
 | WUN-H2-E02-074a | CEILING | D1 0.001 m | 1216Dfl0813263207/02 | m² | Maler- und Lackierarbeiten | 2 | 0.001 | 0 | 1 | Bekleidung | D1 | 0 | 0 | NEW | AllplanAttributes - OKFF: 0
PVC Bahnenware Uni | WUN-H2-E02-075 | FLOORING | Ku2 0.15 m | 1216Bfl0000047515/01 | m² | Bodenbelagsarbeiten | 1 | 0.15 | 0 | 1 | Bodenfläche | Ku2 | 0 | 0 | NEW | AllplanAttributes - Bezeichnung: PVC Bahnenware Uni; Raumnr. Bauherr: 2.11_A2_02; ash B_Aufbau: B9; ash B_Rutschhemmung: R9
Gipsfaserplatten 2-lagig (BSK) | WUN-H2-E02-075 | CEILING | layer 0.036 m | 1216Dfl0000047514/01 | m² | Trockenbauarbeiten | 1 | 0.036 | 0 | 1 | Deckenfläche |  | 0 | 0 | NEW | 3.15 | AllplanAttributes - Bezeichnung: Gipsfaserplatten 2-lagig (BSK); ash_lichte Raumhöhe: 3.4174
Rasterdecke | WUN-H2-E02-075 | CEILING | E3 0.1 m | 1216Dfl0813257037/01 | m² | Trockenbauarbeiten | 1 | 0.1 | 0 | 1 | Bekleidung | E3 | 0 | 0 | NEW | 2.5 | AllplanAttributes - Bezeichnung: Rasterdecke; ash_lichte Raumhöhe: 2.5; Pset_CoveringCommon - AcousticRating: -
PVC Bahnenware Uni | WUN-H2-E02-078 | FLOORING | Ku2 0.15 m | 1216Bfl0000047527/01 | m² | Bodenbelagsarbeiten | 1 | 0.15 | 0 | 1 | Bodenfläche | Ku2 | 0 | 0 | NEW | AllplanAttributes - Bezeichnung: PVC Bahnenware Uni; Raumnr. Bauherr: 2.11_A2_02; ash B_Aufbau: B9; ash B_Rutschhemmung: R9
Gipsfaserplatten 2-lagig (BSK) | WUN-H2-E02-078 | CEILING | layer 0.036 m | 1216Dfl0000047526/01 | m² | Trockenbauarbeiten | 1 | 0.036 | 0 | 1 | Deckenfläche |  | 0 | 0 | NEW | 3.15 | AllplanAttributes - Bezeichnung: Gipsfaserplatten 2-lagig (BSK); ash_lichte Raumhöhe: 3.87594
Rasterdecke | WUN-H2-E02-078 | CEILING | E3 0.1 m | 1216Dfl0813257445/01 | m² | Trockenbauarbeiten | 1 | 0.1 | 0 | 1 | Bekleidung | E3 | 0 | 0 | NEW | 2.5 | AllplanAttributes - Bezeichnung: Rasterdecke; ash_lichte Raumhöhe: 2.5; Pset_CoveringCommon - AcousticRating: -
Fliesen | WUN-H2-E02-079 | FLOORING | Fl1 0.15 m | 1216Bfl0000047539/01 | m² | Bodenbelagsarbeiten | 1 | 0.15 | 0 | 1 | Bodenfläche | Fl1 | 0 | 0 | NEW | AllplanAttributes - Bezeichnung: Fliesen; Raumnr. Bauherr: 2.11_A2_02; ash B_Aufbau: B10; ash B_Rutschhemmung: R10
Gipsfaserplatten 2-lagig (BSK) | WUN-H2-E02-079 | CEILING | layer 0.036 m | 1216Dfl0000047538/01 | m² | Trockenbauarbeiten | 1 | 0.036 | 0 | 1 | Deckenfläche |  | 0 | 0 | NEW | 3.15 | AllplanAttributes - Bezeichnung: Gipsfaserplatten 2-lagig (BSK); ash_lichte Raumhöhe: 3.76083
Rasterdecke | WUN-H2-E02-079 | CEILING | E3 0.1 m | 1216Dfl0813257581/01 | m² | Trockenbauarbeiten | 1 | 0.1 | 0 | 1 | Bekleidung | E3 | 0 | 0 | NEW | 2.5 | AllplanAttributes - Bezeichnung: Rasterdecke; ash_lichte Raumhöhe: 2.5; Pset_CoveringCommon - AcousticRating: -
Fliesen | WUN-H2-E02-080 | FLOORING | Fl1 0.15 m | 1216Bfl0000047551/01 | m² | Bodenbelagsarbeiten | 1 | 0.15 | 0 | 1 | Bodenfläche | Fl1 | 0 | 0 | NEW | AllplanAttributes - Bezeichnung: Fliesen; Raumnr. Bauherr: 2.11_A2_02; ash B_Aufbau: B10; ash B_Rutschhemmung: R10
Gipsfaserplatten 2-lagig (BSK) | WUN-H2-E02-080 | CEILING | layer 0.036 m | 1216Dfl0000047550/01 | m² | Trockenbauarbeiten | 1 | 0.036 | 0 | 1 | Deckenfläche |  | 0 | 0 | NEW | 3.15 | AllplanAttributes - Bezeichnung: Gipsfaserplatten 2-lagig (BSK); ash_lichte Raumhöhe: 3.76083
Rasterdecke | WUN-H2-E02-080 | CEILING | E3 0.1 m | 1216Dfl0813257717/01 | m² | Trockenbauarbeiten | 1 | 0.1 | 0 | 1 | Bekleidung | E3 | 0 | 0 | NEW | 2.5 | AllplanAttributes - Bezeichnung: Rasterdecke; ash_lichte Raumhöhe: 2.5; Pset_CoveringCommon - AcousticRating: -
PVC | WUN-H2-E02-081 | FLOORING | Ku3 0.15 m | 1216Bfl0000047563/01 | m² | Bodenbelagsarbeiten | 1 | 0.15 | 0 | 1 | Bodenfläche | Ku3 | 0 | 0 | NEW | AllplanAttributes - Bezeichnung: PVC; Raumnr. Bauherr: 2.11_A2_02; ash B_Aufbau: B9; ash B_Rutschhemmung: R9
Gipsfaserplatten 2-lagig (BSK) | WUN-H2-E02-081 | CEILING | layer 0.036 m | 1216Dfl0000047562/01 | m² | Trockenbauarbeiten | 1 | 0.036 | 0 | 1 | Deckenfläche |  | 0 | 0 | NEW | 3.15 | AllplanAttributes - Bezeichnung: Gipsfaserplatten 2-lagig (BSK); ash_lichte Raumhöhe: 3.74529
Rasterdecke | WUN-H2-E02-081 | CEILING | E3 0.1 m | 1216Dfl0813257853/01 | m² | Trockenbauarbeiten | 1 | 0.1 | 0 | 1 | Bekleidung | E3 | 0 | 0 | NEW | 2.5 | AllplanAttributes - Bezeichnung: Rasterdecke; ash_lichte Raumhöhe: 2.5; Pset_CoveringCommon - AcousticRating: -
PVC Bahnenware Uni | WUN-H2-E02-077 | FLOORING | Ku2 0.15 m | 1216Bfl0000047491/01 | m² | Bodenbelagsarbeiten | 1 | 0.15 | 0 | 1 | Bodenfläche | Ku2 | 0 | 0 | NEW | AllplanAttributes - Bezeichnung: PVC Bahnenware Uni; Raumnr. Bauherr: 2.11_A2_02; ash B_Aufbau: B9; ash B_Rutschhemmung: R9
Gipsfaserplatten 2-lagig (BSK) | WUN-H2-E02-077 | CEILING | layer 0.036 m | 1216Dfl0000047490/01 | m² | Trockenbauarbeiten | 1 | 0.036 | 0 | 1 | Deckenfläche |  | 0 | 0 | NEW | 3.15 | AllplanAttributes - Bezeichnung: Gipsfaserplatten 2-lagig (BSK); ash_lichte Raumhöhe: 3.87114
Rasterdecke | WUN-H2-E02-077 | CEILING | E3 0.1 m | 1216Dfl0813257309/01 | m² | Trockenbauarbeiten | 1 | 0.1 | 0 | 1 | Bekleidung | E3 | 0 | 0 | NEW | 2.5 | AllplanAttributes - Bezeichnung: Rasterdecke; ash_lichte Raumhöhe: 2.5; Pset_CoveringCommon - AcousticRating: -
Fliesen | WUN-H2-E02-076 | FLOORING | Fl1 0.15 m | 1216Bfl0000047503/01 | m² | Bodenbelagsarbeiten | 1 | 0.15 | 0 | 1 | Bodenfläche | Fl1 | 0 | 0 | NEW | AllplanAttributes - Bezeichnung: Fliesen; Raumnr. Bauherr: 2.11_A2_02; ash B_Aufbau: B10; ash B_Rutschhemmung: R10; ash B_Bewertungsgruppe Barfußbereich: B
Gipsfaserplatten 2-lagig (BSK) | WUN-H2-E02-076 | CEILING | layer 0.036 m | 1216Dfl0000047502/01 | m² | Trockenbauarbeiten | 1 | 0.036 | 0 | 1 | Deckenfläche |  | 0 | 0 | NEW | 3.15 | AllplanAttributes - Bezeichnung: Gipsfaserplatten 2-lagig (BSK); ash_lichte Raumhöhe: 3.65888
 | WUN-H2-E02-076 | CEILING | B 0.1 m | 1216Dfl0813257173/01 | m² | Trockenbauarbeiten | 1 | 0.1 | 0 | 1 | Bekleidung | B | 0 | 0 | NEW | 2.5 | AllplanAttributes - ash_lichte Raumhöhe: 2.5; OKFF: 0; Pset_CoveringCommon - AcousticRating: -
 | WUN-H2-E02-076 | CEILING | D1 0.001 m | 1216Dfl0813257173/02 | m² | Maler- und Lackierarbeiten | 2 | 0.001 | 0 | 1 | Bekleidung | D1 | 0 | 0 | NEW | AllplanAttributes - OKFF: 0
PVC Bahnenware Uni | WUN-H2-E02-089 | FLOORING | Ku2 0.15 m | 1216Bfl0000047598/01 | m² | Bodenbelagsarbeiten | 1 | 0.15 | 0 | 1 | Bodenfläche | Ku2 | 0 | 0 | NEW | AllplanAttributes - Bezeichnung: PVC Bahnenware Uni; Raumnr. Bauherr: 2.11_A2_02; ash B_Aufbau: B9; ash B_Rutschhemmung: R9
Gipsfaserplatten 2-lagig (BSK) | WUN-H2-E02-089 | CEILING | layer 0.036 m | 1216Dfl0000047599/01 | m² | Trockenbauarbeiten | 1 | 0.036 | 0 | 1 | Deckenfläche |  | 0 | 0 | NEW | 3.15 | AllplanAttributes - Bezeichnung: Gipsfaserplatten 2-lagig (BSK); ash_lichte Raumhöhe: 3.42224
Rasterdecke | WUN-H2-E02-089 | CEILING | E3 0.1 m | 1216Dfl0813255674/01 | m² | Trockenbauarbeiten | 1 | 0.1 | 0 | 1 | Bekleidung | E3 | 0 | 0 | NEW | 2.5 | AllplanAttributes - Bezeichnung: Rasterdecke; ash_lichte Raumhöhe: 2.5; Pset_CoveringCommon - AcousticRating: -
PVC Bahnenware Holzoptik | WUN-H2-E02-091 | FLOORING | Ku1 0.15 m | 1216Bfl0000047030/01 | m² | Bodenbelagsarbeiten | 1 | 0.15 | 0 | 1 | Bodenfläche | Ku1 | 0 | 0 | NEW | AllplanAttributes - Bezeichnung: PVC Bahnenware Holzoptik; Raumnr. Bauherr: 2.11_A2_02; ash B_Aufbau: B9; ash B_Rutschhemmung: R9
Acrovyn | WUN-H2-E02-091 | CLADDING | 84 0.001 m | 1216Sfl0812842758/02 | m² | Maler- und Lackierarbeiten | 2 | 0.001 | 0 | 1 | Seitenfläche | 84 | 0 | 0 | NEW | AllplanAttributes - Bezeichnung: Acrovyn
Acrovyn | WUN-H2-E02-091 | CLADDING | 84 0.001 m | 1216Sfl0812842751/02 | m² | Maler- und Lackierarbeiten | 2 | 0.001 | 0 | 1 | Seitenfläche | 84 | 0 | 0 | NEW | AllplanAttributes - Bezeichnung: Acrovyn
Gipsfaserplatten 2-lagig (BSK) | WUN-H2-E02-091 | CEILING | layer 0.036 m | 1216Dfl0000047031/01 | m² | Trockenbauarbeiten | 1 | 0.036 | 0 | 1 | Deckenfläche |  | 0 | 0 | NEW | 3.15 | AllplanAttributes - Bezeichnung: Gipsfaserplatten 2-lagig (BSK); ash_lichte Raumhöhe: 3.95778
 | WUN-H2-E02-091 | CEILING | A1 0.1 m | 1216Dfl0813213254/01 | m² | Trockenbauarbeiten | 1 | 0.1 | 0 | 1 | Bekleidung | A1 | 0 | 0 | NEW | 2.5 | AllplanAttributes - ash_lichte Raumhöhe: 2.5; OKFF: 0; Pset_CoveringCommon - AcousticRating: -
 | WUN-H2-E02-091 | CEILING | D1 0.001 m | 1216Dfl0813213254/02 | m² | Maler- und Lackierarbeiten | 2 | 0.001 | 0 | 1 | Bekleidung | D1 | 0 | 0 | NEW | AllplanAttributes - OKFF: 0
Gipsfaserplatten 2-lagig (BSK) | WUN-H2-E02-091 | CEILING | layer 0.036 m | 1216Dfl0000047042/01 | m² | Trockenbauarbeiten | 1 | 0.036 | 0 | 1 | Deckenfläche |  | 0 | 0 | NEW | 2.5 | AllplanAttributes - Bezeichnung: Gipsfaserplatten 2-lagig (BSK); ash_lichte Raumhöhe: 3.1555
 | WUN-H2-E02-091 | CEILING | Installationshöhe 0.764 m | 1216Dfl0000047042/02 | m² | Trockenbauarbeiten | 2 | 0.764 | 0 | 1 | Bekleidung | Installationshöhe | 0 | 0 | NEW | AllplanAttributes - OKFF: 0
 | WUN-H2-E02-091 | CEILING | A1 0.1 m | 1216Dfl0000047042/03 | m² | Trockenbauarbeiten | 3 | 0.1 | 0 | 1 | Bekleidung | A1 | 0 | 0 | NEW | Pset_CoveringCommon - AcousticRating: -; AllplanAttributes - OKFF: 0
 | WUN-H2-E02-091 | CEILING | D1 0.001 m | 1216Dfl0000047042/04 | m² | Maler- und Lackierarbeiten | 4 | 0.001 | 0 | 1 | Bekleidung | D1 | 0 | 0 | NEW | AllplanAttributes - OKFF: 0
 | WUN-H2-E02-091 | CEILING | A1 0.1 m | 1216Dfl0813211715/01 | m² | Trockenbauarbeiten | 1 | 0.1 | 0 | 1 | Bekleidung | A1 | 0 | 0 | NEW | 2.5 | AllplanAttributes - ash_lichte Raumhöhe: 3.150000; OKFF: 0; Pset_CoveringCommon - AcousticRating: -
 | WUN-H2-E02-091 | CEILING | D1 0.001 m | 1216Dfl0813211715/02 | m² | Maler- und Lackierarbeiten | 2 | 0.001 | 0 | 1 | Bekleidung | D1 | 0 | 0 | NEW | 2.5 | AllplanAttributes - ash_lichte Raumhöhe: 3.150000; OKFF: 0
Fliesen | WUN-H2-E02-095a | FLOORING | Fl1 0.15 m | 1216Bfl0000046914/01 | m² | Bodenbelagsarbeiten | 1 | 0.15 | 0 | 1 | Bodenfläche | Fl1 | 0 | 0 | NEW | AllplanAttributes - Bezeichnung: Fliesen; Raumnr. Bauherr: 2.11_A2_02; ash B_Aufbau: B10; ash B_Rutschhemmung: R10
Fliesen Mosaik | WUN-H2-E02-095a | FLOORING | Fl2 0.15 m | 1216Bfl0813117465/01 | m² | Bodenbelagsarbeiten | 1 | 0.15 | 0 | 1 | Bodenfläche | Fl2 | 0 | 0 | NEW | AllplanAttributes - Bezeichnung: Fliesen Mosaik; Raumnr. Bauherr: 2.11_A2_02; ash B_Aufbau: B11; ash B_Rutschhemmung: R10; ash B_Bewertungsgruppe Barfußbereich: B
Gipsfaserplatten 2-lagig (BSK) | WUN-H2-E02-095a | CEILING | layer 0.036 m | 1216Dfl0000046915/01 | m² | Trockenbauarbeiten | 1 | 0.036 | 0 | 1 | Deckenfläche |  | 0 | 0 | NEW | 3.15 | AllplanAttributes - Bezeichnung: Gipsfaserplatten 2-lagig (BSK); ash_lichte Raumhöhe: 5.55698
 | WUN-H2-E02-095a | CEILING | B 0.1 m | 1216Dfl0813214474/01 | m² | Trockenbauarbeiten | 1 | 0.1 | 0 | 1 | Bekleidung | B | 0 | 0 | NEW | 2.5 | AllplanAttributes - ash_lichte Raumhöhe: 2.5; OKFF: 0; Pset_CoveringCommon - AcousticRating: -
 | WUN-H2-E02-095a | CEILING | D1 0.001 m | 1216Dfl0813214474/02 | m² | Maler- und Lackierarbeiten | 2 | 0.001 | 0 | 1 | Bekleidung | D1 | 0 | 0 | NEW | AllplanAttributes - OKFF: 0
Fliesen | WUN-H2-E02-094a | FLOORING | Fl1 0.15 m | 1216Bfl0000046926/01 | m² | Bodenbelagsarbeiten | 1 | 0.15 | 0 | 1 | Bodenfläche | Fl1 | 0 | 0 | NEW | AllplanAttributes - Bezeichnung: Fliesen; Raumnr. Bauherr: 2.11_A2_02; ash B_Aufbau: B10; ash B_Rutschhemmung: R10
Fliesen Mosaik | WUN-H2-E02-094a | FLOORING | Fl2 0.15 m | 1216Bfl0813117665/01 | m² | Bodenbelagsarbeiten | 1 | 0.15 | 0 | 1 | Bodenfläche | Fl2 | 0 | 0 | NEW | AllplanAttributes - Bezeichnung: Fliesen Mosaik; Raumnr. Bauherr: 2.11_A2_02; ash B_Aufbau: B11; ash B_Rutschhemmung: R10; ash B_Bewertungsgruppe Barfußbereich: B
Gipsfaserplatten 2-lagig (BSK) | WUN-H2-E02-094a | CEILING | layer 0.036 m | 1216Dfl0000046927/01 | m² | Trockenbauarbeiten | 1 | 0.036 | 0 | 1 | Deckenfläche |  | 0 | 0 | NEW | 3.15 | AllplanAttributes - Bezeichnung: Gipsfaserplatten 2-lagig (BSK); ash_lichte Raumhöhe: 5.36446
 | WUN-H2-E02-094a | CEILING | B 0.1 m | 1216Dfl0813214338/01 | m² | Trockenbauarbeiten | 1 | 0.1 | 0 | 1 | Bekleidung | B | 0 | 0 | NEW | 2.5 | AllplanAttributes - ash_lichte Raumhöhe: 2.5; OKFF: 0; Pset_CoveringCommon - AcousticRating: -
 | WUN-H2-E02-094a | CEILING | D1 0.001 m | 1216Dfl0813214338/02 | m² | Maler- und Lackierarbeiten | 2 | 0.001 | 0 | 1 | Bekleidung | D1 | 0 | 0 | NEW | AllplanAttributes - OKFF: 0
Fliesen | WUN-H2-E02-093a | FLOORING | Fl1 0.15 m | 1216Bfl0000046992/01 | m² | Bodenbelagsarbeiten | 1 | 0.15 | 0 | 1 | Bodenfläche | Fl1 | 0 | 0 | NEW | AllplanAttributes - Bezeichnung: Fliesen; Raumnr. Bauherr: 2.11_A2_02; ash B_Aufbau: B10; ash B_Rutschhemmung: R10
Fliesen Mosaik | WUN-H2-E02-093a | FLOORING | Fl2 0.15 m | 1216Bfl0813117865/01 | m² | Bodenbelagsarbeiten | 1 | 0.15 | 0 | 1 | Bodenfläche | Fl2 | 0 | 0 | NEW | AllplanAttributes - Bezeichnung: Fliesen Mosaik; Raumnr. Bauherr: 2.11_A2_02; ash B_Aufbau: B11; ash B_Rutschhemmung: R10; ash B_Bewertungsgruppe Barfußbereich: B
Gipsfaserplatten 2-lagig (BSK) | WUN-H2-E02-093a | CEILING | layer 0.036 m | 1216Dfl0000046993/01 | m² | Trockenbauarbeiten | 1 | 0.036 | 0 | 1 | Deckenfläche |  | 0 | 0 | NEW | 3.15 | AllplanAttributes - Bezeichnung: Gipsfaserplatten 2-lagig (BSK); ash_lichte Raumhöhe: 4.7519
 | WUN-H2-E02-093a | CEILING | B 0.1 m | 1216Dfl0813214202/01 | m² | Trockenbauarbeiten | 1 | 0.1 | 0 | 1 | Bekleidung | B | 0 | 0 | NEW | 2.5 | AllplanAttributes - ash_lichte Raumhöhe: 2.5; OKFF: 0; Pset_CoveringCommon - AcousticRating: -
 | WUN-H2-E02-093a | CEILING | D1 0.001 m | 1216Dfl0813214202/02 | m² | Maler- und Lackierarbeiten | 2 | 0.001 | 0 | 1 | Bekleidung | D1 | 0 | 0 | NEW | AllplanAttributes - OKFF: 0
Fliesen | WUN-H2-E02-092a | FLOORING | Fl1 0.15 m | 1216Bfl0000047004/01 | m² | Bodenbelagsarbeiten | 1 | 0.15 | 0 | 1 | Bodenfläche | Fl1 | 0 | 0 | NEW | AllplanAttributes - Bezeichnung: Fliesen; Raumnr. Bauherr: 2.11_A2_02; ash B_Aufbau: B10; ash B_Rutschhemmung: R10
Fliesen Mosaik | WUN-H2-E02-092a | FLOORING | Fl2 0.15 m | 1216Bfl0813118065/01 | m² | Bodenbelagsarbeiten | 1 | 0.15 | 0 | 1 | Bodenfläche | Fl2 | 0 | 0 | NEW | AllplanAttributes - Bezeichnung: Fliesen Mosaik; Raumnr. Bauherr: 2.11_A2_02; ash B_Aufbau: B11; ash B_Rutschhemmung: R10; ash B_Bewertungsgruppe Barfußbereich: B
Gipsfaserplatten 2-lagig (BSK) | WUN-H2-E02-092a | CEILING | layer 0.036 m | 1216Dfl0000047005/01 | m² | Trockenbauarbeiten | 1 | 0.036 | 0 | 1 | Deckenfläche |  | 0 | 0 | NEW | 3.15 | AllplanAttributes - Bezeichnung: Gipsfaserplatten 2-lagig (BSK); ash_lichte Raumhöhe: 4.5211
 | WUN-H2-E02-092a | CEILING | B 0.1 m | 1216Dfl0813214058/01 | m² | Trockenbauarbeiten | 1 | 0.1 | 0 | 1 | Bekleidung | B | 0 | 0 | NEW | 2.5 | AllplanAttributes - ash_lichte Raumhöhe: 2.5; OKFF: 0; Pset_CoveringCommon - AcousticRating: -
 | WUN-H2-E02-092a | CEILING | D1 0.001 m | 1216Dfl0813214058/02 | m² | Maler- und Lackierarbeiten | 2 | 0.001 | 0 | 1 | Bekleidung | D1 | 0 | 0 | NEW | AllplanAttributes - OKFF: 0
Fliesen | WUN-H2-E02-096a | FLOORING | Fl1 0.15 m | 1216Bfl0000046888/01 | m² | Bodenbelagsarbeiten | 1 | 0.15 | 0 | 1 | Bodenfläche | Fl1 | 0 | 0 | NEW | AllplanAttributes - Bezeichnung: Fliesen; Raumnr. Bauherr: 2.11_A2_02; ash B_Aufbau: B10; ash B_Rutschhemmung: R10
Fliesen Mosaik | WUN-H2-E02-096a | FLOORING | Fl2 0.15 m | 1216Bfl0813117265/01 | m² | Bodenbelagsarbeiten | 1 | 0.15 | 0 | 1 | Bodenfläche | Fl2 | 0 | 0 | NEW | AllplanAttributes - Bezeichnung: Fliesen Mosaik; Raumnr. Bauherr: 2.11_A2_02; ash B_Aufbau: B11; ash B_Rutschhemmung: R10; ash B_Bewertungsgruppe Barfußbereich: B
Gipsfaserplatten 2-lagig (BSK) | WUN-H2-E02-096a | CEILING | layer 0.036 m | 1216Dfl0000046889/01 | m² | Trockenbauarbeiten | 1 | 0.036 | 0 | 1 | Deckenfläche |  | 0 | 0 | NEW | 3.15 | AllplanAttributes - Bezeichnung: Gipsfaserplatten 2-lagig (BSK); ash_lichte Raumhöhe: 4.43305
 | WUN-H2-E02-096a | CEILING | B 0.1 m | 1216Dfl0813214610/01 | m² | Trockenbauarbeiten | 1 | 0.1 | 0 | 1 | Bekleidung | B | 0 | 0 | NEW | 2.5 | AllplanAttributes - ash_lichte Raumhöhe: 2.5; OKFF: 0; Pset_CoveringCommon - AcousticRating: -
 | WUN-H2-E02-096a | CEILING | D1 0.001 m | 1216Dfl0813214610/02 | m² | Maler- und Lackierarbeiten | 2 | 0.001 | 0 | 1 | Bekleidung | D1 | 0 | 0 | NEW | AllplanAttributes - OKFF: 0
PVC Bahnenware Holzoptik | WUN-H2-E02-095 | FLOORING | Ku1 0.15 m | 1216Bfl0000046900/01 | m² | Bodenbelagsarbeiten | 1 | 0.15 | 0 | 1 | Bodenfläche | Ku1 | 0 | 0 | NEW | AllplanAttributes - Bezeichnung: PVC Bahnenware Holzoptik; Raumnr. Bauherr: 2.11_A2_02; ash B_Aufbau: B9; ash B_Rutschhemmung: R9
Acrovyn | WUN-H2-E02-095 | CLADDING | 84 0.001 m | 1216Sfl0812842766/02 | m² | Maler- und Lackierarbeiten | 2 | 0.001 | 0 | 1 | Seitenfläche | 84 | 0 | 0 | NEW | AllplanAttributes - Bezeichnung: Acrovyn
Acrovyn | WUN-H2-E02-095 | CLADDING | 84 0.001 m | 1216Sfl0812842745/02 | m² | Maler- und Lackierarbeiten | 2 | 0.001 | 0 | 1 | Seitenfläche | 84 | 0 | 0 | NEW | AllplanAttributes - Bezeichnung: Acrovyn
 | WUN-H2-E02-095 | CEILING | A1 0.1 m | 1216Dfl0000046912/01 | m² | Trockenbauarbeiten | 1 | 0.1 | 0 | 1 | Bekleidung | A1 | 0 | 0 | NEW | 2.5 | AllplanAttributes - ash_lichte Raumhöhe: 2.5; OKFF: 0; Pset_CoveringCommon - AcousticRating: -
 | WUN-H2-E02-095 | CEILING | D1 0.001 m | 1216Dfl0000046912/02 | m² | Maler- und Lackierarbeiten | 2 | 0.001 | 0 | 1 | Bekleidung | D1 | 0 | 0 | NEW | AllplanAttributes - OKFF: 0
Gipsfaserplatten 2-lagig (BSK) | WUN-H2-E02-095 | CEILING | layer 0.036 m | 1216Dfl0000046901/01 | m² | Trockenbauarbeiten | 1 | 0.036 | 0 | 1 | Deckenfläche |  | 0 | 0 | NEW | 3.15 | AllplanAttributes - Bezeichnung: Gipsfaserplatten 2-lagig (BSK); ash_lichte Raumhöhe: 5.7076
 | WUN-H2-E02-095 | CEILING | A1 0.1 m | 1216Dfl0813217162/01 | m² | Trockenbauarbeiten | 1 | 0.1 | 0 | 1 | Bekleidung | A1 | 0 | 0 | NEW | 2.5 | AllplanAttributes - ash_lichte Raumhöhe: 3.150000; OKFF: 0; Pset_CoveringCommon - AcousticRating: -
 | WUN-H2-E02-095 | CEILING | D1 0.001 m | 1216Dfl0813217162/02 | m² | Maler- und Lackierarbeiten | 2 | 0.001 | 0 | 1 | Bekleidung | D1 | 0 | 0 | NEW | 2.5 | AllplanAttributes - ash_lichte Raumhöhe: 3.150000; OKFF: 0
PVC Bahnenware Holzoptik | WUN-H2-E02-094 | FLOORING | Ku1 0.15 m | 1216Bfl0000046938/01 | m² | Bodenbelagsarbeiten | 1 | 0.15 | 0 | 1 | Bodenfläche | Ku1 | 0 | 0 | NEW | AllplanAttributes - Bezeichnung: PVC Bahnenware Holzoptik; Raumnr. Bauherr: 2.11_A2_02; ash B_Aufbau: B9; ash B_Rutschhemmung: R9
Acrovyn | WUN-H2-E02-094 | CLADDING | 84 0.001 m | 1216Sfl0812842764/02 | m² | Maler- und Lackierarbeiten | 2 | 0.001 | 0 | 1 | Seitenfläche | 84 | 0 | 0 | NEW | AllplanAttributes - Bezeichnung: Acrovyn
Acrovyn | WUN-H2-E02-094 | CLADDING | 84 0.001 m | 1216Sfl0812842747/02 | m² | Maler- und Lackierarbeiten | 2 | 0.001 | 0 | 1 | Seitenfläche | 84 | 0 | 0 | NEW | AllplanAttributes - Bezeichnung: Acrovyn
 | WUN-H2-E02-094 | CEILING | A1 0.1 m | 1216Dfl0000046950/01 | m² | Trockenbauarbeiten | 1 | 0.1 | 0 | 1 | Bekleidung | A1 | 0 | 0 | NEW | 2.5 | AllplanAttributes - ash_lichte Raumhöhe: 2.5; OKFF: 0; Pset_CoveringCommon - AcousticRating: -
 | WUN-H2-E02-094 | CEILING | D1 0.001 m | 1216Dfl0000046950/02 | m² | Maler- und Lackierarbeiten | 2 | 0.001 | 0 | 1 | Bekleidung | D1 | 0 | 0 | NEW | AllplanAttributes - OKFF: 0
Gipsfaserplatten 2-lagig (BSK) | WUN-H2-E02-094 | CEILING | layer 0.036 m | 1216Dfl0000046939/01 | m² | Trockenbauarbeiten | 1 | 0.036 | 0 | 1 | Deckenfläche |  | 0 | 0 | NEW | 3.15 | AllplanAttributes - Bezeichnung: Gipsfaserplatten 2-lagig (BSK); ash_lichte Raumhöhe: 5.21787
 | WUN-H2-E02-094 | CEILING | A1 0.1 m | 1216Dfl0813216770/01 | m² | Trockenbauarbeiten | 1 | 0.1 | 0 | 1 | Bekleidung | A1 | 0 | 0 | NEW | 2.5 | AllplanAttributes - ash_lichte Raumhöhe: 3.150000; OKFF: 0; Pset_CoveringCommon - AcousticRating: -
 | WUN-H2-E02-094 | CEILING | D1 0.001 m | 1216Dfl0813216770/02 | m² | Maler- und Lackierarbeiten | 2 | 0.001 | 0 | 1 | Bekleidung | D1 | 0 | 0 | NEW | 2.5 | AllplanAttributes - ash_lichte Raumhöhe: 3.150000; OKFF: 0
PVC Bahnenware Holzoptik | WUN-H2-E02-093 | FLOORING | Ku1 0.15 m | 1216Bfl0000046978/01 | m² | Bodenbelagsarbeiten | 1 | 0.15 | 0 | 1 | Bodenfläche | Ku1 | 0 | 0 | NEW | AllplanAttributes - Bezeichnung: PVC Bahnenware Holzoptik; Raumnr. Bauherr: 2.11_A2_02; ash B_Aufbau: B9; ash B_Rutschhemmung: R9
Acrovyn | WUN-H2-E02-093 | CLADDING | 84 0.001 m | 1216Sfl0812842762/02 | m² | Maler- und Lackierarbeiten | 2 | 0.001 | 0 | 1 | Seitenfläche | 84 | 0 | 0 | NEW | AllplanAttributes - Bezeichnung: Acrovyn
Gipsfaserplatten 2-lagig (BSK) | WUN-H2-E02-093 | CEILING | layer 0.036 m | 1216Dfl0000046979/01 | m² | Trockenbauarbeiten | 1 | 0.036 | 0 | 1 | Deckenfläche |  | 0 | 0 | NEW | 3.15 | AllplanAttributes - Bezeichnung: Gipsfaserplatten 2-lagig (BSK); ash_lichte Raumhöhe: 4.86403
 | WUN-H2-E02-093 | CEILING | A1 0.1 m | 1216Dfl0000046990/01 | m² | Trockenbauarbeiten | 1 | 0.1 | 0 | 1 | Bekleidung | A1 | 0 | 0 | NEW | 2.5 | AllplanAttributes - ash_lichte Raumhöhe: 2.5; OKFF: 0; Pset_CoveringCommon - AcousticRating: -
 | WUN-H2-E02-093 | CEILING | D1 0.001 m | 1216Dfl0000046990/02 | m² | Maler- und Lackierarbeiten | 2 | 0.001 | 0 | 1 | Bekleidung | D1 | 0 | 0 | NEW | AllplanAttributes - OKFF: 0
 | WUN-H2-E02-093 | CEILING | A1 0.1 m | 1216Dfl0813216378/01 | m² | Trockenbauarbeiten | 1 | 0.1 | 0 | 1 | Bekleidung | A1 | 0 | 0 | NEW | 2.5 | AllplanAttributes - ash_lichte Raumhöhe: 3.150000; OKFF: 0; Pset_CoveringCommon - AcousticRating: -
 | WUN-H2-E02-093 | CEILING | D1 0.001 m | 1216Dfl0813216378/02 | m² | Maler- und Lackierarbeiten | 2 | 0.001 | 0 | 1 | Bekleidung | D1 | 0 | 0 | NEW | 2.5 | AllplanAttributes - ash_lichte Raumhöhe: 3.150000; OKFF: 0
PVC Bahnenware Holzoptik | WUN-H2-E02-092 | FLOORING | Ku1 0.15 m | 1216Bfl0000047016/01 | m² | Bodenbelagsarbeiten | 1 | 0.15 | 0 | 1 | Bodenfläche | Ku1 | 0 | 0 | NEW | AllplanAttributes - Bezeichnung: PVC Bahnenware Holzoptik; Raumnr. Bauherr: 2.11_A2_02; ash B_Aufbau: B9; ash B_Rutschhemmung: R9
Acrovyn | WUN-H2-E02-092 | CLADDING | 84 0.001 m | 1216Sfl0812842760/02 | m² | Maler- und Lackierarbeiten | 2 | 0.001 | 0 | 1 | Seitenfläche | 84 | 0 | 0 | NEW | AllplanAttributes - Bezeichnung: Acrovyn
Acrovyn | WUN-H2-E02-092 | CLADDING | 84 0.001 m | 1216Sfl0812842749/02 | m² | Maler- und Lackierarbeiten | 2 | 0.001 | 0 | 1 | Seitenfläche | 84 | 0 | 0 | NEW | AllplanAttributes - Bezeichnung: Acrovyn
Gipsfaserplatten 2-lagig (BSK) | WUN-H2-E02-092 | CEILING | layer 0.036 m | 1216Dfl0000047017/01 | m² | Trockenbauarbeiten | 1 | 0.036 | 0 | 1 | Deckenfläche |  | 0 | 0 | NEW | 3.15 | AllplanAttributes - Bezeichnung: Gipsfaserplatten 2-lagig (BSK); ash_lichte Raumhöhe: 4.36916
 | WUN-H2-E02-092 | CEILING | A1 0.1 m | 1216Dfl0000047028/01 | m² | Trockenbauarbeiten | 1 | 0.1 | 0 | 1 | Bekleidung | A1 | 0 | 0 | NEW | 2.5 | AllplanAttributes - ash_lichte Raumhöhe: 2.5; OKFF: 0; Pset_CoveringCommon - AcousticRating: -
 | WUN-H2-E02-092 | CEILING | D1 0.001 m | 1216Dfl0000047028/02 | m² | Maler- und Lackierarbeiten | 2 | 0.001 | 0 | 1 | Bekleidung | D1 | 0 | 0 | NEW | AllplanAttributes - OKFF: 0
 | WUN-H2-E02-092 | CEILING | A1 0.1 m | 1216Dfl0813306177/01 | m² | Trockenbauarbeiten | 1 | 0.1 | 0 | 1 | Bekleidung | A1 | 0 | 0 | NEW | 2.5 | AllplanAttributes - ash_lichte Raumhöhe: 3.150000; OKFF: 0; Pset_CoveringCommon - AcousticRating: -
 | WUN-H2-E02-092 | CEILING | D1 0.001 m | 1216Dfl0813306177/02 | m² | Maler- und Lackierarbeiten | 2 | 0.001 | 0 | 1 | Bekleidung | D1 | 0 | 0 | NEW | 2.5 | AllplanAttributes - ash_lichte Raumhöhe: 3.150000; OKFF: 0
PVC Bahnenware Holzoptik | WUN-H2-E02-096 | FLOORING | Ku1 0.15 m | 1216Bfl0000046874/01 | m² | Bodenbelagsarbeiten | 1 | 0.15 | 0 | 1 | Bodenfläche | Ku1 | 0 | 0 | NEW | AllplanAttributes - Bezeichnung: PVC Bahnenware Holzoptik; Raumnr. Bauherr: 2.11_A2_02; ash B_Aufbau: B9; ash B_Rutschhemmung: R9
Acrovyn | WUN-H2-E02-096 | CLADDING | 84 0.001 m | 1216Sfl0812842743/02 | m² | Maler- und Lackierarbeiten | 2 | 0.001 | 0 | 1 | Seitenfläche | 84 | 0 | 0 | NEW | AllplanAttributes - Bezeichnung: Acrovyn
Acrovyn | WUN-H2-E02-096 | CLADDING | 84 0.001 m | 1216Sfl0812842768/02 | m² | Maler- und Lackierarbeiten | 2 | 0.001 | 0 | 1 | Seitenfläche | 84 | 0 | 0 | NEW | AllplanAttributes - Bezeichnung: Acrovyn
 | WUN-H2-E02-096 | CEILING | A1 0.1 m | 1216Dfl0000046886/01 | m² | Trockenbauarbeiten | 1 | 0.1 | 0 | 1 | Bekleidung | A1 | 0 | 0 | NEW | 2.5 | AllplanAttributes - ash_lichte Raumhöhe: 2.5; OKFF: 0; Pset_CoveringCommon - AcousticRating: -
 | WUN-H2-E02-096 | CEILING | D1 0.001 m | 1216Dfl0000046886/02 | m² | Maler- und Lackierarbeiten | 2 | 0.001 | 0 | 1 | Bekleidung | D1 | 0 | 0 | NEW | AllplanAttributes - OKFF: 0
Gipsfaserplatten 2-lagig (BSK) | WUN-H2-E02-096 | CEILING | layer 0.036 m | 1216Dfl0000046875/01 | m² | Trockenbauarbeiten | 1 | 0.036 | 0 | 1 | Deckenfläche |  | 0 | 0 | NEW | 3.15 | AllplanAttributes - Bezeichnung: Gipsfaserplatten 2-lagig (BSK); ash_lichte Raumhöhe: 4.81892
 | WUN-H2-E02-096 | CEILING | A1 0.1 m | 1216Dfl0813217554/01 | m² | Trockenbauarbeiten | 1 | 0.1 | 0 | 1 | Bekleidung | A1 | 0 | 0 | NEW | 2.5 | AllplanAttributes - ash_lichte Raumhöhe: 3.150000; OKFF: 0; Pset_CoveringCommon - AcousticRating: -
 | WUN-H2-E02-096 | CEILING | D1 0.001 m | 1216Dfl0813217554/02 | m² | Maler- und Lackierarbeiten | 2 | 0.001 | 0 | 1 | Bekleidung | D1 | 0 | 0 | NEW | 2.5 | AllplanAttributes - ash_lichte Raumhöhe: 3.150000; OKFF: 0
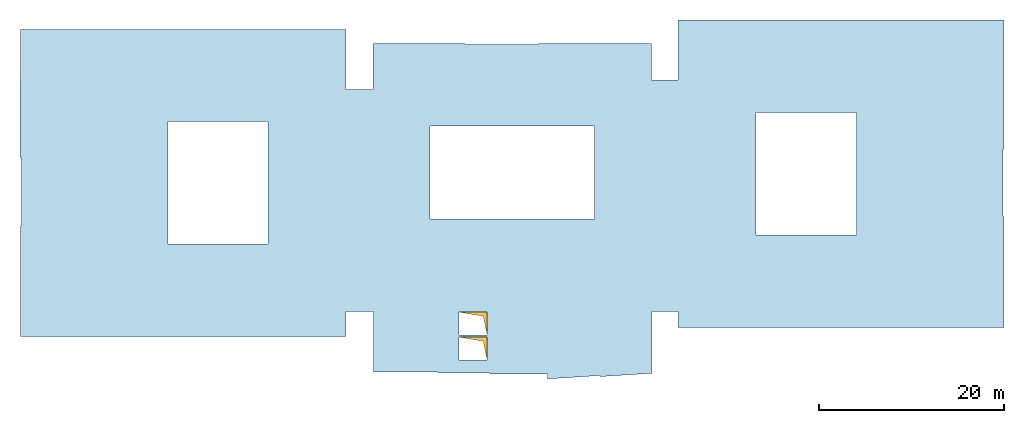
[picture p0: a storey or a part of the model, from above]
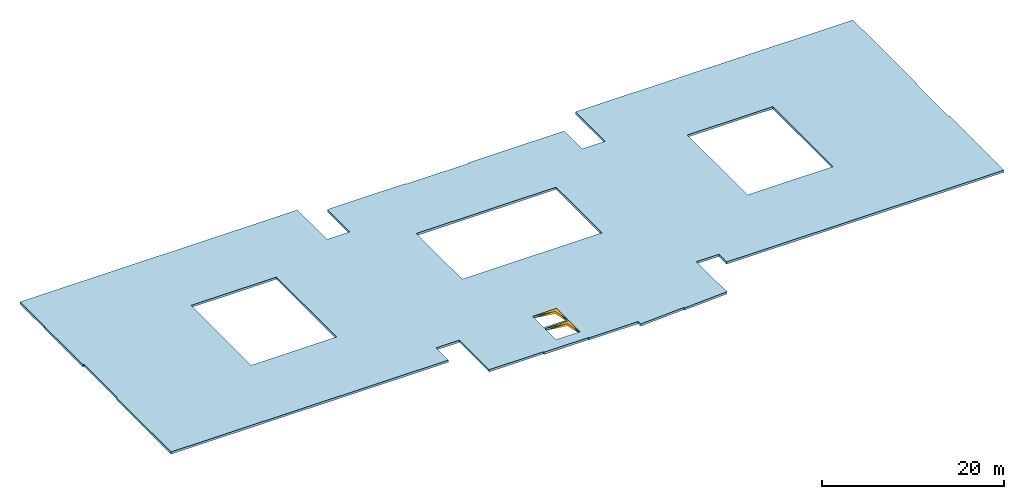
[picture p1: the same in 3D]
Properties of the parts of a building model (IFC4), part 9 of 80

# IfcCovering (3945)
Name | In | PredefinedType | Material | Allright_Bauteil_ID | Abrechnungsart | Gewerk | Schichtnummer | Schichtdicke (m) | Dicke (m) | Faktor | Objektname | AllplanAttributes, Material | Bezugshöhe | Deltahöhe | Status | D_lichte Raumhöhe [Zahl] (m)
Fliesen | WUN-H2-E02-091a | FLOORING | Fl1 0.15 m | 1216Bfl0000047044/01 | m² | Bodenbelagsarbeiten | 1 | 0.15 | 0 | 1 | Bodenfläche | Fl1 | 0 | 0 | NEW | AllplanAttributes - Bezeichnung: Fliesen; Raumnr. Bauherr: 2.11_A2_02; ash B_Aufbau: B10; ash B_Rutschhemmung: R10
Fliesen Mosaik | WUN-H2-E02-091a | FLOORING | Fl2 0.15 m | 1216Bfl0813118265/01 | m² | Bodenbelagsarbeiten | 1 | 0.15 | 0 | 1 | Bodenfläche | Fl2 | 0 | 0 | NEW | AllplanAttributes - Bezeichnung: Fliesen Mosaik; Raumnr. Bauherr: 2.11_A2_02; ash B_Aufbau: B11; ash B_Rutschhemmung: R10; ash B_Bewertungsgruppe Barfußbereich: B
Gipsfaserplatten 2-lagig (BSK) | WUN-H2-E02-091a | CEILING | layer 0.036 m | 1216Dfl0000047045/01 | m² | Trockenbauarbeiten | 1 | 0.036 | 0 | 1 | Deckenfläche |  | 0 | 0 | NEW | 3.15 | AllplanAttributes - Bezeichnung: Gipsfaserplatten 2-lagig (BSK); ash_lichte Raumhöhe: 3.81119
 | WUN-H2-E02-091a | CEILING | B 0.1 m | 1216Dfl0813212662/01 | m² | Trockenbauarbeiten | 1 | 0.1 | 0 | 1 | Bekleidung | B | 0 | 0 | NEW | 2.5 | AllplanAttributes - ash_lichte Raumhöhe: 2.5; OKFF: 0; Pset_CoveringCommon - AcousticRating: -
 | WUN-H2-E02-091a | CEILING | D1 0.001 m | 1216Dfl0813212662/02 | m² | Maler- und Lackierarbeiten | 2 | 0.001 | 0 | 1 | Bekleidung | D1 | 0 | 0 | NEW | AllplanAttributes - OKFF: 0
Fliesen | WUN-H2-E02-090a | FLOORING | Fl1 0.15 m | 1216Bfl0000047056/01 | m² | Bodenbelagsarbeiten | 1 | 0.15 | 0 | 1 | Bodenfläche | Fl1 | 0 | 0 | NEW | AllplanAttributes - Bezeichnung: Fliesen; Raumnr. Bauherr: 2.11_A2_02; ash B_Aufbau: B10; ash B_Rutschhemmung: R10
Fliesen Mosaik | WUN-H2-E02-090a | FLOORING | Fl2 0.15 m | 1216Bfl0813118465/01 | m² | Bodenbelagsarbeiten | 1 | 0.15 | 0 | 1 | Bodenfläche | Fl2 | 0 | 0 | NEW | AllplanAttributes - Bezeichnung: Fliesen Mosaik; Raumnr. Bauherr: 2.11_A2_02; ash B_Aufbau: B11; ash B_Rutschhemmung: R10; ash B_Bewertungsgruppe Barfußbereich: B
Gipsfaserplatten 2-lagig (BSK) | WUN-H2-E02-090a | CEILING | layer 0.036 m | 1216Dfl0000047057/01 | m² | Trockenbauarbeiten | 1 | 0.036 | 0 | 1 | Deckenfläche |  | 0 | 0 | NEW | 3.15 | AllplanAttributes - Bezeichnung: Gipsfaserplatten 2-lagig (BSK); ash_lichte Raumhöhe: 3.61867
 | WUN-H2-E02-090a | CEILING | B 0.1 m | 1216Dfl0813211122/01 | m² | Trockenbauarbeiten | 1 | 0.1 | 0 | 1 | Bekleidung | B | 0 | 0 | NEW | 2.5 | AllplanAttributes - ash_lichte Raumhöhe: 2.5; OKFF: 0; Pset_CoveringCommon - AcousticRating: -
 | WUN-H2-E02-090a | CEILING | D1 0.001 m | 1216Dfl0813211122/02 | m² | Maler- und Lackierarbeiten | 2 | 0.001 | 0 | 1 | Bekleidung | D1 | 0 | 0 | NEW | AllplanAttributes - OKFF: 0
PVC Bahnenware Holzoptik | WUN-H2-E02-090 | FLOORING | Ku1 0.15 m | 1216Bfl0000047068/01 | m² | Bodenbelagsarbeiten | 1 | 0.15 | 0 | 1 | Bodenfläche | Ku1 | 0 | 0 | NEW | AllplanAttributes - Bezeichnung: PVC Bahnenware Holzoptik; Raumnr. Bauherr: 2.11_A2_02; ash B_Aufbau: B9; ash B_Rutschhemmung: R9
Acrovyn | WUN-H2-E02-090 | CLADDING | 84 0.001 m | 1216Sfl0812842755/02 | m² | Maler- und Lackierarbeiten | 2 | 0.001 | 0 | 1 | Seitenfläche | 84 | 0 | 0 | NEW | AllplanAttributes - Bezeichnung: Acrovyn
Acrovyn | WUN-H2-E02-090 | CLADDING | 84 0.001 m | 1216Sfl0812842753/02 | m² | Maler- und Lackierarbeiten | 2 | 0.001 | 0 | 1 | Seitenfläche | 84 | 0 | 0 | NEW | AllplanAttributes - Bezeichnung: Acrovyn
Gipsfaserplatten 2-lagig (BSK) | WUN-H2-E02-090 | CEILING | layer 0.036 m | 1216Dfl0000047069/01 | m² | Trockenbauarbeiten | 1 | 0.036 | 0 | 1 | Deckenfläche |  | 0 | 0 | NEW | 3.15 | AllplanAttributes - Bezeichnung: Gipsfaserplatten 2-lagig (BSK); ash_lichte Raumhöhe: 3.47056
 | WUN-H2-E02-090 | CEILING | A1 0.1 m | 1216Dfl0000047080/01 | m² | Trockenbauarbeiten | 1 | 0.1 | 0 | 1 | Bekleidung | A1 | 0 | 0 | NEW | 2.5 | AllplanAttributes - ash_lichte Raumhöhe: 2.5; OKFF: 0; Pset_CoveringCommon - AcousticRating: -
 | WUN-H2-E02-090 | CEILING | D1 0.001 m | 1216Dfl0000047080/02 | m² | Maler- und Lackierarbeiten | 2 | 0.001 | 0 | 1 | Bekleidung | D1 | 0 | 0 | NEW | AllplanAttributes - OKFF: 0
 | WUN-H2-E02-090 | CEILING | A1 0.1 m | 1216Dfl0813171538/01 | m² | Trockenbauarbeiten | 1 | 0.1 | 0 | 1 | Bekleidung | A1 | 0 | 0 | NEW | 2.5 | AllplanAttributes - ash_lichte Raumhöhe: 3.150000; OKFF: 0; Pset_CoveringCommon - AcousticRating: -
 | WUN-H2-E02-090 | CEILING | D1 0.001 m | 1216Dfl0813171538/02 | m² | Maler- und Lackierarbeiten | 2 | 0.001 | 0 | 1 | Bekleidung | D1 | 0 | 0 | NEW | 2.5 | AllplanAttributes - ash_lichte Raumhöhe: 3.150000; OKFF: 0
PVC Bahnenware Holzoptik | WUN-H2-E02-056 | FLOORING | Ku1 0.15 m | 1216Bfl0000047122/01 | m² | Bodenbelagsarbeiten | 1 | 0.15 | 0 | 1 | Bodenfläche | Ku1 | 0 | 0 | NEW | AllplanAttributes - Bezeichnung: PVC Bahnenware Holzoptik; Raumnr. Bauherr: 2.11_A2_02; ash B_Aufbau: B9; ash B_Rutschhemmung: R9
Gipsfaserplatten 2-lagig (BSK) | WUN-H2-E02-056 | CEILING | layer 0.036 m | 1216Dfl0812853928/01 | m² | Trockenbauarbeiten | 1 | 0.036 | 0 | 1 | Deckenfläche |  | 0 | 0 | NEW | 2.5 | AllplanAttributes - Bezeichnung: Gipsfaserplatten 2-lagig (BSK); ash_lichte Raumhöhe: 2.5
 | WUN-H2-E02-056 | CEILING | Installationshöhe 0.714 m | 1216Dfl0812853928/02 | m² | Trockenbauarbeiten | 2 | 0.714 | 0 | 1 | Bekleidung | Installationshöhe | 0 | 0 | NEW | AllplanAttributes - OKFF: 0
 | WUN-H2-E02-056 | CEILING | Aa 0.15 m | 1216Dfl0812853928/03 | m² | Trockenbauarbeiten | 3 | 0.15 | 0 | 1 | Bekleidung | Aa | 0 | 0 | NEW | Pset_CoveringCommon - AcousticRating: -; AllplanAttributes - OKFF: 0
 | WUN-H2-E02-056 | CEILING | D1 0.001 m | 1216Dfl0812853928/04 | m² | Maler- und Lackierarbeiten | 4 | 0.001 | 0 | 1 | Bekleidung | D1 | 0 | 0 | NEW | AllplanAttributes - OKFF: 0
Gipsfaserplatten 2-lagig (BSK) | WUN-H2-E02-056 | CEILING | layer 0.036 m | 1216Dfl0000047134/01 | m² | Trockenbauarbeiten | 1 | 0.036 | 0 | 1 | Deckenfläche |  | 0 | 0 | NEW | 2.5 | AllplanAttributes - Bezeichnung: Gipsfaserplatten 2-lagig (BSK); ash_lichte Raumhöhe: 2.5
 | WUN-H2-E02-056 | CEILING | Installationshöhe 0.714 m | 1216Dfl0000047134/02 | m² | Trockenbauarbeiten | 2 | 0.714 | 0 | 1 | Bekleidung | Installationshöhe | 0 | 0 | NEW | AllplanAttributes - OKFF: 0
 | WUN-H2-E02-056 | CEILING | A1 0.15 m | 1216Dfl0000047134/03 | m² | Trockenbauarbeiten | 3 | 0.15 | 0 | 1 | Bekleidung | A1 | 0 | 0 | NEW | Pset_CoveringCommon - AcousticRating: -; AllplanAttributes - OKFF: 0
 | WUN-H2-E02-056 | CEILING | D1 0.001 m | 1216Dfl0000047134/04 | m² | Maler- und Lackierarbeiten | 4 | 0.001 | 0 | 1 | Bekleidung | D1 | 0 | 0 | NEW | AllplanAttributes - OKFF: 0
PVC Bahnenware Holzoptik | WUN-H2-E02-059 | FLOORING | Ku1 0.15 m | 1216Bfl0000046964/01 | m² | Bodenbelagsarbeiten | 1 | 0.15 | 0 | 1 | Bodenfläche | Ku1 | 0 | 0 | NEW | AllplanAttributes - Bezeichnung: PVC Bahnenware Holzoptik; Raumnr. Bauherr: 2.11_A2_02; ash B_Aufbau: B9; ash B_Rutschhemmung: R9
Gipsfaserplatten 2-lagig (BSK) | WUN-H2-E02-059 | CEILING | layer 0.036 m | 1216Dfl0812855696/01 | m² | Trockenbauarbeiten | 1 | 0.036 | 0 | 1 | Deckenfläche |  | 0 | 0 | NEW | 2.5 | AllplanAttributes - Bezeichnung: Gipsfaserplatten 2-lagig (BSK); ash_lichte Raumhöhe: 2.5
 | WUN-H2-E02-059 | CEILING | Installationshöhe 0.714 m | 1216Dfl0812855696/02 | m² | Trockenbauarbeiten | 2 | 0.714 | 0 | 1 | Bekleidung | Installationshöhe | 0 | 0 | NEW | AllplanAttributes - OKFF: 0
 | WUN-H2-E02-059 | CEILING | Aa 0.15 m | 1216Dfl0812855696/03 | m² | Trockenbauarbeiten | 3 | 0.15 | 0 | 1 | Bekleidung | Aa | 0 | 0 | NEW | Pset_CoveringCommon - AcousticRating: -; AllplanAttributes - OKFF: 0
 | WUN-H2-E02-059 | CEILING | D1 0.001 m | 1216Dfl0812855696/04 | m² | Maler- und Lackierarbeiten | 4 | 0.001 | 0 | 1 | Bekleidung | D1 | 0 | 0 | NEW | AllplanAttributes - OKFF: 0
Gipsfaserplatten 2-lagig (BSK) | WUN-H2-E02-059 | CEILING | layer 0.036 m | 1216Dfl0000046976/01 | m² | Trockenbauarbeiten | 1 | 0.036 | 0 | 1 | Deckenfläche |  | 0 | 0 | NEW | 2.5 | AllplanAttributes - Bezeichnung: Gipsfaserplatten 2-lagig (BSK); ash_lichte Raumhöhe: 2.5
 | WUN-H2-E02-059 | CEILING | Installationshöhe 0.714 m | 1216Dfl0000046976/02 | m² | Trockenbauarbeiten | 2 | 0.714 | 0 | 1 | Bekleidung | Installationshöhe | 0 | 0 | NEW | AllplanAttributes - OKFF: 0
 | WUN-H2-E02-059 | CEILING | A1 0.15 m | 1216Dfl0000046976/03 | m² | Trockenbauarbeiten | 3 | 0.15 | 0 | 1 | Bekleidung | A1 | 0 | 0 | NEW | Pset_CoveringCommon - AcousticRating: -; AllplanAttributes - OKFF: 0
 | WUN-H2-E02-059 | CEILING | D1 0.001 m | 1216Dfl0000046976/04 | m² | Maler- und Lackierarbeiten | 4 | 0.001 | 0 | 1 | Bekleidung | D1 | 0 | 0 | NEW | AllplanAttributes - OKFF: 0
PVC Bahnenware Holzoptik | WUN-H2-E02-013a | FLOORING | Ku1 0.15 m | 1216Bfl0812652327/01 | m² | Bodenbelagsarbeiten | 1 | 0.15 | 0 | 1 | Bodenfläche | Ku1 | 0 | 0 | NEW | AllplanAttributes - Bezeichnung: PVC Bahnenware Holzoptik; Raumnr. Bauherr: 2.11_A2_02; ash B_Aufbau: B9; ash B_Rutschhemmung: R9
Gipsfaserplatten 2-lagig (BSK) | WUN-H2-E02-013a | CEILING | layer 0.036 m | 1216Dfl0812849836/01 | m² | Trockenbauarbeiten | 1 | 0.036 | 0 | 1 | Deckenfläche |  | 0 | 0 | NEW | 2.75 | AllplanAttributes - Bezeichnung: Gipsfaserplatten 2-lagig (BSK); ash_lichte Raumhöhe: 2.75
 | WUN-H2-E02-013a | CEILING | Installationshöhe 0.464 m | 1216Dfl0812849836/02 | m² | Trockenbauarbeiten | 2 | 0.464 | 0 | 1 | Bekleidung | Installationshöhe | 0 | 0 | NEW
 | WUN-H2-E02-013a | CEILING | Aa 0.15 m | 1216Dfl0812849836/03 | m² | Trockenbauarbeiten | 3 | 0.15 | 0 | 1 | Bekleidung | Aa | 0 | 0 | NEW | Pset_CoveringCommon - AcousticRating: -
 | WUN-H2-E02-013a | CEILING | D1 0.001 m | 1216Dfl0812849836/04 | m² | Maler- und Lackierarbeiten | 4 | 0.001 | 0 | 1 | Bekleidung | D1 | 0 | 0 | NEW
Gipsfaserplatten 2-lagig (BSK) | WUN-H2-E02-013a | CEILING | layer 0.036 m | 1216Dfl0812652356/01 | m² | Trockenbauarbeiten | 1 | 0.036 | 0 | 1 | Deckenfläche |  | 0 | 0 | NEW | 2.75 | AllplanAttributes - Bezeichnung: Gipsfaserplatten 2-lagig (BSK); ash_lichte Raumhöhe: 2.75
 | WUN-H2-E02-013a | CEILING | Installationshöhe 0.464 m | 1216Dfl0812652356/02 | m² | Trockenbauarbeiten | 2 | 0.464 | 0 | 1 | Bekleidung | Installationshöhe | 0 | 0 | NEW
 | WUN-H2-E02-013a | CEILING | A1 0.15 m | 1216Dfl0812652356/03 | m² | Trockenbauarbeiten | 3 | 0.15 | 0 | 1 | Bekleidung | A1 | 0 | 0 | NEW | Pset_CoveringCommon - AcousticRating: -
 | WUN-H2-E02-013a | CEILING | D1 0.001 m | 1216Dfl0812652356/04 | m² | Maler- und Lackierarbeiten | 4 | 0.001 | 0 | 1 | Bekleidung | D1 | 0 | 0 | NEW
Gipsfaserplatten 2-lagig (BSK) | WUN-H2-E02-013a | CEILING | layer 0.036 m | 1216Dfl0812850416/01 | m² | Trockenbauarbeiten | 1 | 0.036 | 0 | 1 | Deckenfläche |  | 0 | 0 | NEW | 2.75 | AllplanAttributes - Bezeichnung: Gipsfaserplatten 2-lagig (BSK); ash_lichte Raumhöhe: 2.75
 | WUN-H2-E02-013a | CEILING | Installationshöhe 0.464 m | 1216Dfl0812850416/02 | m² | Trockenbauarbeiten | 2 | 0.464 | 0 | 1 | Bekleidung | Installationshöhe | 0 | 0 | NEW
 | WUN-H2-E02-013a | CEILING | Aa 0.15 m | 1216Dfl0812850416/03 | m² | Trockenbauarbeiten | 3 | 0.15 | 0 | 1 | Bekleidung | Aa | 0 | 0 | NEW | Pset_CoveringCommon - AcousticRating: -
 | WUN-H2-E02-013a | CEILING | D1 0.001 m | 1216Dfl0812850416/04 | m² | Maler- und Lackierarbeiten | 4 | 0.001 | 0 | 1 | Bekleidung | D1 | 0 | 0 | NEW
PVC Bahnenware Uni | WUN-H2-E02-051 | FLOORING | Ku2 0.15 m | 1216Bfl0000047148/01 | m² | Bodenbelagsarbeiten | 1 | 0.15 | 0 | 1 | Bodenfläche | Ku2 | 0 | 0 | NEW | AllplanAttributes - Bezeichnung: PVC Bahnenware Uni; Raumnr. Bauherr: 2.11_A2_02; ash B_Aufbau: B9; ash B_Rutschhemmung: R9
Gipsfaserplatten 2-lagig (BSK) | WUN-H2-E02-051 | CEILING | layer 0.036 m | 1216Dfl0812652943/01 | m² | Trockenbauarbeiten | 1 | 0.036 | 0 | 1 | Deckenfläche |  | 0 | 0 | NEW | 2.5 | AllplanAttributes - Bezeichnung: Gipsfaserplatten 2-lagig (BSK); ash_lichte Raumhöhe: 2.5
 | WUN-H2-E02-051 | CEILING | Installationshöhe 0.764 m | 1216Dfl0812652943/02 | m² | Trockenbauarbeiten | 2 | 0.764 | 0 | 1 | Bekleidung | Installationshöhe | 0 | 0 | NEW | AllplanAttributes - OKFF: 0
 | WUN-H2-E02-051 | CEILING | A1 0.1 m | 1216Dfl0812652943/03 | m² | Trockenbauarbeiten | 3 | 0.1 | 0 | 1 | Bekleidung | A1 | 0 | 0 | NEW | Pset_CoveringCommon - AcousticRating: -; AllplanAttributes - OKFF: 0
 | WUN-H2-E02-051 | CEILING | D1 0.001 m | 1216Dfl0812652943/04 | m² | Maler- und Lackierarbeiten | 4 | 0.001 | 0 | 1 | Bekleidung | D1 | 0 | 0 | NEW | AllplanAttributes - OKFF: 0
PVC Bahnenware Holzoptik | WUN-H2-E02-058 | FLOORING | Ku1 0.15 m | 1216Bfl0000047082/01 | m² | Bodenbelagsarbeiten | 1 | 0.15 | 0 | 1 | Bodenfläche | Ku1 | 0 | 0 | NEW | AllplanAttributes - Bezeichnung: PVC Bahnenware Holzoptik; Raumnr. Bauherr: 2.11_A2_02; ash B_Aufbau: B9; ash B_Rutschhemmung: R9
Gipsfaserplatten 2-lagig (BSK) | WUN-H2-E02-058 | CEILING | layer 0.036 m | 1216Dfl0000047094/01 | m² | Trockenbauarbeiten | 1 | 0.036 | 0 | 1 | Deckenfläche |  | 0 | 0 | NEW | 2.5 | AllplanAttributes - Bezeichnung: Gipsfaserplatten 2-lagig (BSK); ash_lichte Raumhöhe: 2.5
 | WUN-H2-E02-058 | CEILING | Installationshöhe 0.714 m | 1216Dfl0000047094/02 | m² | Trockenbauarbeiten | 2 | 0.714 | 0 | 1 | Bekleidung | Installationshöhe | 0 | 0 | NEW | AllplanAttributes - OKFF: 0
 | WUN-H2-E02-058 | CEILING | A1 0.15 m | 1216Dfl0000047094/03 | m² | Trockenbauarbeiten | 3 | 0.15 | 0 | 1 | Bekleidung | A1 | 0 | 0 | NEW | Pset_CoveringCommon - AcousticRating: -; AllplanAttributes - OKFF: 0
 | WUN-H2-E02-058 | CEILING | D1 0.001 m | 1216Dfl0000047094/04 | m² | Maler- und Lackierarbeiten | 4 | 0.001 | 0 | 1 | Bekleidung | D1 | 0 | 0 | NEW | AllplanAttributes - OKFF: 0
Gipsfaserplatten 2-lagig (BSK) | WUN-H2-E02-058 | CEILING | layer 0.036 m | 1216Dfl0812855103/01 | m² | Trockenbauarbeiten | 1 | 0.036 | 0 | 1 | Deckenfläche |  | 0 | 0 | NEW | 2.5 | AllplanAttributes - Bezeichnung: Gipsfaserplatten 2-lagig (BSK); ash_lichte Raumhöhe: 2.5
 | WUN-H2-E02-058 | CEILING | Installationshöhe 0.714 m | 1216Dfl0812855103/02 | m² | Trockenbauarbeiten | 2 | 0.714 | 0 | 1 | Bekleidung | Installationshöhe | 0 | 0 | NEW | AllplanAttributes - OKFF: 0
 | WUN-H2-E02-058 | CEILING | Aa 0.15 m | 1216Dfl0812855103/03 | m² | Trockenbauarbeiten | 3 | 0.15 | 0 | 1 | Bekleidung | Aa | 0 | 0 | NEW | Pset_CoveringCommon - AcousticRating: -; AllplanAttributes - OKFF: 0
 | WUN-H2-E02-058 | CEILING | D1 0.001 m | 1216Dfl0812855103/04 | m² | Maler- und Lackierarbeiten | 4 | 0.001 | 0 | 1 | Bekleidung | D1 | 0 | 0 | NEW | AllplanAttributes - OKFF: 0
PVC Bahnenware Uni | WUN-H2-E02-011 | FLOORING | Ku2 0.15 m | 1216Bfl0000046578/01 | m² | Bodenbelagsarbeiten | 1 | 0.15 | 0 | 1 | Bodenfläche | Ku2 | 0 | 0 | NEW | AllplanAttributes - Bezeichnung: PVC Bahnenware Uni; Raumnr. Bauherr: 2.11_A2_02; ash B_Aufbau: B9; ash B_Rutschhemmung: R9
Gipsfaserplatten 2-lagig (BSK) | WUN-H2-E02-011 | CEILING | layer 0.036 m | 1216Dfl0000046590/01 | m² | Trockenbauarbeiten | 1 | 0.036 | 0 | 1 | Deckenfläche |  | 0 | 0 | NEW | 2.5 | AllplanAttributes - Bezeichnung: Gipsfaserplatten 2-lagig (BSK); ash_lichte Raumhöhe: 2.5
Kühldecke glatt | WUN-H2-E02-011 | CEILING | Installationshöhe 0.764 m | 1216Dfl0000046590/02 | m² | Trockenbauarbeiten | 2 | 0.764 | 0 | 1 | Bekleidung | Installationshöhe | 0 | 0 | NEW | AllplanAttributes - OKFF: 0
Kühldecke glatt | WUN-H2-E02-011 | CEILING | H7a 0.1 m | 1216Dfl0000046590/03 | m² | Trockenbauarbeiten | 3 | 0.1 | 0 | 1 | Bekleidung | H7a | 0 | 0 | NEW | AllplanAttributes - Bezeichnung: Kühldecke glatt; OKFF: 0; Pset_CoveringCommon - AcousticRating: -
Kühldecke glatt | WUN-H2-E02-011 | CEILING | D1 0.001 m | 1216Dfl0000046590/04 | m² | Maler- und Lackierarbeiten | 4 | 0.001 | 0 | 1 | Bekleidung | D1 | 0 | 0 | NEW | AllplanAttributes - OKFF: 0
PVC Bahnenware Uni | WUN-H2-E02-065 | FLOORING | Ku2 0.15 m | 1216Bfl0000047186/01 | m² | Bodenbelagsarbeiten | 1 | 0.15 | 0 | 1 | Bodenfläche | Ku2 | 0 | 0 | NEW | AllplanAttributes - Bezeichnung: PVC Bahnenware Uni; Raumnr. Bauherr: 2.11_A2_02; ash B_Aufbau: B9; ash B_Rutschhemmung: R9
Gipsfaserplatten 2-lagig (BSK) | WUN-H2-E02-065 | CEILING | layer 0.036 m | 1216Dfl0000047198/01 | m² | Trockenbauarbeiten | 1 | 0.036 | 0 | 1 | Deckenfläche |  | 0 | 0 | NEW | 2.5 | AllplanAttributes - Bezeichnung: Gipsfaserplatten 2-lagig (BSK); ash_lichte Raumhöhe: 2.5
 | WUN-H2-E02-065 | CEILING | Installationshöhe 0.764 m | 1216Dfl0000047198/02 | m² | Trockenbauarbeiten | 2 | 0.764 | 0 | 1 | Bekleidung | Installationshöhe | 0 | 0 | NEW | AllplanAttributes - OKFF: 0
Kühldecke glatt | WUN-H2-E02-065 | CEILING | H7a 0.1 m | 1216Dfl0000047198/03 | m² | Trockenbauarbeiten | 3 | 0.1 | 0 | 1 | Bekleidung | H7a | 0 | 0 | NEW | AllplanAttributes - Bezeichnung: Kühldecke glatt; OKFF: 0; Pset_CoveringCommon - AcousticRating: -
 | WUN-H2-E02-065 | CEILING | D1 0.001 m | 1216Dfl0000047198/04 | m² | Maler- und Lackierarbeiten | 4 | 0.001 | 0 | 1 | Bekleidung | D1 | 0 | 0 | NEW | AllplanAttributes - OKFF: 0
PVC Bahnenware Holzoptik | WUN-H2-E02-066 | FLOORING | Ku1 0.15 m | 1216Bfl0000047172/01 | m² | Bodenbelagsarbeiten | 1 | 0.15 | 0 | 1 | Bodenfläche | Ku1 | 0 | 0 | NEW | AllplanAttributes - Bezeichnung: PVC Bahnenware Holzoptik; Raumnr. Bauherr: 2.11_A2_02; ash B_Aufbau: B9; ash B_Rutschhemmung: R9
Gipsfaserplatten 2-lagig (BSK) | WUN-H2-E02-066 | CEILING | layer 0.036 m | 1216Dfl0813000916/01 | m² | Trockenbauarbeiten | 1 | 0.036 | 0 | 1 | Deckenfläche |  | 0 | 0 | NEW | 2.5 | AllplanAttributes - Bezeichnung: Gipsfaserplatten 2-lagig (BSK); ash_lichte Raumhöhe: 2.5
 | WUN-H2-E02-066 | CEILING | Installationshöhe 0.764 m | 1216Dfl0813000916/02 | m² | Trockenbauarbeiten | 2 | 0.764 | 0 | 1 | Bekleidung | Installationshöhe | 0 | 0 | NEW | AllplanAttributes - OKFF: 0
Kühldecke gelocht | WUN-H2-E02-066 | CEILING | H7b 0.1 m | 1216Dfl0813000916/03 | m² | Trockenbauarbeiten | 3 | 0.1 | 0 | 1 | Bekleidung | H7b | 0 | 0 | NEW | AllplanAttributes - Bezeichnung: Kühldecke gelocht; OKFF: 0; Pset_CoveringCommon - AcousticRating: -
 | WUN-H2-E02-066 | CEILING | D1 0.001 m | 1216Dfl0813000916/04 | m² | Maler- und Lackierarbeiten | 4 | 0.001 | 0 | 1 | Bekleidung | D1 | 0 | 0 | NEW | AllplanAttributes - OKFF: 0
Gipsfaserplatten 2-lagig (BSK) | WUN-H2-E02-066 | CEILING | layer 0.036 m | 1216Dfl0000047184/01 | m² | Trockenbauarbeiten | 1 | 0.036 | 0 | 1 | Deckenfläche |  | 0 | 0 | NEW | 2.5 | AllplanAttributes - Bezeichnung: Gipsfaserplatten 2-lagig (BSK); ash_lichte Raumhöhe: 2.5
 | WUN-H2-E02-066 | CEILING | Installationshöhe 0.764 m | 1216Dfl0000047184/02 | m² | Trockenbauarbeiten | 2 | 0.764 | 0 | 1 | Bekleidung | Installationshöhe | 0 | 0 | NEW | AllplanAttributes - OKFF: 0
Kühldecke glatt | WUN-H2-E02-066 | CEILING | H7a 0.1 m | 1216Dfl0000047184/03 | m² | Trockenbauarbeiten | 3 | 0.1 | 0 | 1 | Bekleidung | H7a | 0 | 0 | NEW | AllplanAttributes - Bezeichnung: Kühldecke glatt; OKFF: 0; Pset_CoveringCommon - AcousticRating: -
 | WUN-H2-E02-066 | CEILING | D1 0.001 m | 1216Dfl0000047184/04 | m² | Maler- und Lackierarbeiten | 4 | 0.001 | 0 | 1 | Bekleidung | D1 | 0 | 0 | NEW | AllplanAttributes - OKFF: 0
PVC Bahnenware Holzoptik | WUN-H2-E02-064a | FLOORING | Ku1 0.15 m | 1216Bfl0812652340/01 | m² | Bodenbelagsarbeiten | 1 | 0.15 | 0 | 1 | Bodenfläche | Ku1 | 0 | 0 | NEW | AllplanAttributes - Bezeichnung: PVC Bahnenware Holzoptik; Raumnr. Bauherr: 2.11_A2_02; ash B_Aufbau: B9; ash B_Rutschhemmung: R9
Gipsfaserplatten 2-lagig (BSK) | WUN-H2-E02-064a | CEILING | layer 0.036 m | 1216Dfl0812652652/01 | m² | Trockenbauarbeiten | 1 | 0.036 | 0 | 1 | Deckenfläche |  | 0 | 0 | NEW | 2.5 | AllplanAttributes - Bezeichnung: Gipsfaserplatten 2-lagig (BSK); ash_lichte Raumhöhe: 2.5
 | WUN-H2-E02-064a | CEILING | Installationshöhe 0.764 m | 1216Dfl0812652652/02 | m² | Trockenbauarbeiten | 2 | 0.764 | 0 | 1 | Bekleidung | Installationshöhe | 0 | 0 | NEW | AllplanAttributes - OKFF: 0
Kühldecke glatt | WUN-H2-E02-064a | CEILING | H7a 0.1 m | 1216Dfl0812652652/03 | m² | Trockenbauarbeiten | 3 | 0.1 | 0 | 1 | Bekleidung | H7a | 0 | 0 | NEW | AllplanAttributes - Bezeichnung: Kühldecke glatt; OKFF: 0; Pset_CoveringCommon - AcousticRating: -
 | WUN-H2-E02-064a | CEILING | D1 0.001 m | 1216Dfl0812652652/04 | m² | Maler- und Lackierarbeiten | 4 | 0.001 | 0 | 1 | Bekleidung | D1 | 0 | 0 | NEW | AllplanAttributes - OKFF: 0
Gipsfaserplatten 2-lagig (BSK) | WUN-H2-E02-064a | CEILING | layer 0.036 m | 1216Dfl0812999756/01 | m² | Trockenbauarbeiten | 1 | 0.036 | 0 | 1 | Deckenfläche |  | 0 | 0 | NEW | 2.5 | AllplanAttributes - Bezeichnung: Gipsfaserplatten 2-lagig (BSK); ash_lichte Raumhöhe: 2.5
Kühldecke gelocht | WUN-H2-E02-064a | CEILING | Installationshöhe 0.764 m | 1216Dfl0812999756/02 | m² | Trockenbauarbeiten | 2 | 0.764 | 0 | 1 | Bekleidung | Installationshöhe | 0 | 0 | NEW | AllplanAttributes - OKFF: 0
Kühldecke gelocht | WUN-H2-E02-064a | CEILING | H7b 0.1 m | 1216Dfl0812999756/03 | m² | Trockenbauarbeiten | 3 | 0.1 | 0 | 1 | Bekleidung | H7b | 0 | 0 | NEW | AllplanAttributes - Bezeichnung: Kühldecke gelocht; OKFF: 0; Pset_CoveringCommon - AcousticRating: -
Kühldecke gelocht | WUN-H2-E02-064a | CEILING | D1 0.001 m | 1216Dfl0812999756/04 | m² | Maler- und Lackierarbeiten | 4 | 0.001 | 0 | 1 | Bekleidung | D1 | 0 | 0 | NEW | AllplanAttributes - OKFF: 0
PVC Bahnenware Holzoptik | WUN-H2-E02-012a | FLOORING | Ku1 0.15 m | 1216Bfl0000046643/01 | m² | Bodenbelagsarbeiten | 1 | 0.15 | 0 | 1 | Bodenfläche | Ku1 | 0 | 0 | NEW | AllplanAttributes - Bezeichnung: PVC Bahnenware Holzoptik; Raumnr. Bauherr: 2.11_A2_02; ash B_Aufbau: B9; ash B_Rutschhemmung: R9
Gipsfaserplatten 2-lagig (BSK) | WUN-H2-E02-012a | CEILING | layer 0.036 m | 1216Dfl0000046654/01 | m² | Trockenbauarbeiten | 1 | 0.036 | 0 | 1 | Deckenfläche |  | 0 | 0 | NEW | 2.5 | AllplanAttributes - Bezeichnung: Gipsfaserplatten 2-lagig (BSK); ash_lichte Raumhöhe: 2.5
 | WUN-H2-E02-012a | CEILING | Installationshöhe 0.764 m | 1216Dfl0000046654/02 | m² | Trockenbauarbeiten | 2 | 0.764 | 0 | 1 | Bekleidung | Installationshöhe | 0 | 0 | NEW | AllplanAttributes - OKFF: 0
Kühldecke glatt | WUN-H2-E02-012a | CEILING | H7a 0.1 m | 1216Dfl0000046654/03 | m² | Trockenbauarbeiten | 3 | 0.1 | 0 | 1 | Bekleidung | H7a | 0 | 0 | NEW | AllplanAttributes - Bezeichnung: Kühldecke glatt; OKFF: 0; Pset_CoveringCommon - AcousticRating: -
 | WUN-H2-E02-012a | CEILING | D1 0.001 m | 1216Dfl0000046654/04 | m² | Maler- und Lackierarbeiten | 4 | 0.001 | 0 | 1 | Bekleidung | D1 | 0 | 0 | NEW | AllplanAttributes - OKFF: 0
Gipsfaserplatten 2-lagig (BSK) | WUN-H2-E02-012a | CEILING | layer 0.036 m | 1216Dfl0812999176/01 | m² | Trockenbauarbeiten | 1 | 0.036 | 0 | 1 | Deckenfläche |  | 0 | 0 | NEW | 2.5 | AllplanAttributes - Bezeichnung: Gipsfaserplatten 2-lagig (BSK); ash_lichte Raumhöhe: 2.5
 | WUN-H2-E02-012a | CEILING | Installationshöhe 0.764 m | 1216Dfl0812999176/02 | m² | Trockenbauarbeiten | 2 | 0.764 | 0 | 1 | Bekleidung | Installationshöhe | 0 | 0 | NEW | AllplanAttributes - OKFF: 0
Kühldecke gelocht | WUN-H2-E02-012a | CEILING | H7b 0.1 m | 1216Dfl0812999176/03 | m² | Trockenbauarbeiten | 3 | 0.1 | 0 | 1 | Bekleidung | H7b | 0 | 0 | NEW | AllplanAttributes - Bezeichnung: Kühldecke gelocht; OKFF: 0; Pset_CoveringCommon - AcousticRating: -
 | WUN-H2-E02-012a | CEILING | D1 0.001 m | 1216Dfl0812999176/04 | m² | Maler- und Lackierarbeiten | 4 | 0.001 | 0 | 1 | Bekleidung | D1 | 0 | 0 | NEW | AllplanAttributes - OKFF: 0
PVC Bahnenware Holzoptik | WUN-H2-E02-005 | FLOORING | Ku1 0.15 m | 1216Bfl0000046410/01 | m² | Bodenbelagsarbeiten | 1 | 0.15 | 0 | 1 | Bodenfläche | Ku1 | 0 | 0 | NEW | AllplanAttributes - Bezeichnung: PVC Bahnenware Holzoptik; Raumnr. Bauherr: 2.11_A2_02; ash B_Aufbau: B9; ash B_Rutschhemmung: R9
Gipsfaserplatten 2-lagig (BSK) | WUN-H2-E02-005 | CEILING | layer 0.036 m | 1216Dfl0000046422/01 | m² | Trockenbauarbeiten | 1 | 0.036 | 0 | 1 | Deckenfläche |  | 0 | 0 | NEW | 2.5 | AllplanAttributes - Bezeichnung: Gipsfaserplatten 2-lagig (BSK); ash_lichte Raumhöhe: 2.5
 | WUN-H2-E02-005 | CEILING | Installationshöhe 0.714 m | 1216Dfl0000046422/02 | m² | Trockenbauarbeiten | 2 | 0.714 | 0 | 1 | Bekleidung | Installationshöhe | 0 | 0 | NEW | AllplanAttributes - OKFF: 0
 | WUN-H2-E02-005 | CEILING | A1 0.15 m | 1216Dfl0000046422/03 | m² | Trockenbauarbeiten | 3 | 0.15 | 0 | 1 | Bekleidung | A1 | 0 | 0 | NEW | Pset_CoveringCommon - AcousticRating: -; AllplanAttributes - OKFF: 0
 | WUN-H2-E02-005 | CEILING | D1 0.001 m | 1216Dfl0000046422/04 | m² | Maler- und Lackierarbeiten | 4 | 0.001 | 0 | 1 | Bekleidung | D1 | 0 | 0 | NEW | AllplanAttributes - OKFF: 0
Gipsfaserplatten 2-lagig (BSK) | WUN-H2-E02-005 | CEILING | layer 0.036 m | 1216Dfl0812845730/01 | m² | Trockenbauarbeiten | 1 | 0.036 | 0 | 1 | Deckenfläche |  | 0 | 0 | NEW | 2.5 | AllplanAttributes - Bezeichnung: Gipsfaserplatten 2-lagig (BSK); ash_lichte Raumhöhe: 2.5
 | WUN-H2-E02-005 | CEILING | Installationshöhe 0.714 m | 1216Dfl0812845730/02 | m² | Trockenbauarbeiten | 2 | 0.714 | 0 | 1 | Bekleidung | Installationshöhe | 0 | 0 | NEW | AllplanAttributes - OKFF: 0
 | WUN-H2-E02-005 | CEILING | Aa 0.15 m | 1216Dfl0812845730/03 | m² | Trockenbauarbeiten | 3 | 0.15 | 0 | 1 | Bekleidung | Aa | 0 | 0 | NEW | Pset_CoveringCommon - AcousticRating: -; AllplanAttributes - OKFF: 0
 | WUN-H2-E02-005 | CEILING | D1 0.001 m | 1216Dfl0812845730/04 | m² | Maler- und Lackierarbeiten | 4 | 0.001 | 0 | 1 | Bekleidung | D1 | 0 | 0 | NEW | AllplanAttributes - OKFF: 0
PVC Bahnenware Holzoptik | WUN-H2-E02-004 | FLOORING | Ku1 0.15 m | 1216Bfl0000046396/01 | m² | Bodenbelagsarbeiten | 1 | 0.15 | 0 | 1 | Bodenfläche | Ku1 | 0 | 0 | NEW | AllplanAttributes - Bezeichnung: PVC Bahnenware Holzoptik; Raumnr. Bauherr: 2.11_A2_02; ash B_Aufbau: B9; ash B_Rutschhemmung: R9
Gipsfaserplatten 2-lagig (BSK) | WUN-H2-E02-004 | CEILING | layer 0.036 m | 1216Dfl0812846322/01 | m² | Trockenbauarbeiten | 1 | 0.036 | 0 | 1 | Deckenfläche |  | 0 | 0 | NEW | 2.5 | AllplanAttributes - Bezeichnung: Gipsfaserplatten 2-lagig (BSK); ash_lichte Raumhöhe: 2.5
 | WUN-H2-E02-004 | CEILING | Installationshöhe 0.714 m | 1216Dfl0812846322/02 | m² | Trockenbauarbeiten | 2 | 0.714 | 0 | 1 | Bekleidung | Installationshöhe | 0 | 0 | NEW | AllplanAttributes - OKFF: 0
 | WUN-H2-E02-004 | CEILING | Aa 0.15 m | 1216Dfl0812846322/03 | m² | Trockenbauarbeiten | 3 | 0.15 | 0 | 1 | Bekleidung | Aa | 0 | 0 | NEW | Pset_CoveringCommon - AcousticRating: -; AllplanAttributes - OKFF: 0
 | WUN-H2-E02-004 | CEILING | D1 0.001 m | 1216Dfl0812846322/04 | m² | Maler- und Lackierarbeiten | 4 | 0.001 | 0 | 1 | Bekleidung | D1 | 0 | 0 | NEW | AllplanAttributes - OKFF: 0
Gipsfaserplatten 2-lagig (BSK) | WUN-H2-E02-004 | CEILING | layer 0.036 m | 1216Dfl0000046408/01 | m² | Trockenbauarbeiten | 1 | 0.036 | 0 | 1 | Deckenfläche |  | 0 | 0 | NEW | 2.5 | AllplanAttributes - Bezeichnung: Gipsfaserplatten 2-lagig (BSK); ash_lichte Raumhöhe: 2.5
 | WUN-H2-E02-004 | CEILING | Installationshöhe 0.714 m | 1216Dfl0000046408/02 | m² | Trockenbauarbeiten | 2 | 0.714 | 0 | 1 | Bekleidung | Installationshöhe | 0 | 0 | NEW | AllplanAttributes - OKFF: 0
 | WUN-H2-E02-004 | CEILING | A1 0.15 m | 1216Dfl0000046408/03 | m² | Trockenbauarbeiten | 3 | 0.15 | 0 | 1 | Bekleidung | A1 | 0 | 0 | NEW | Pset_CoveringCommon - AcousticRating: -; AllplanAttributes - OKFF: 0
 | WUN-H2-E02-004 | CEILING | D1 0.001 m | 1216Dfl0000046408/04 | m² | Maler- und Lackierarbeiten | 4 | 0.001 | 0 | 1 | Bekleidung | D1 | 0 | 0 | NEW | AllplanAttributes - OKFF: 0
PVC Bahnenware Holzoptik | WUN-H2-E02-007 | FLOORING | Ku1 0.15 m | 1216Bfl0000046438/01 | m² | Bodenbelagsarbeiten | 1 | 0.15 | 0 | 1 | Bodenfläche | Ku1 | 0 | 0 | NEW | AllplanAttributes - Bezeichnung: PVC Bahnenware Holzoptik; Raumnr. Bauherr: 2.11_A2_02; ash B_Aufbau: B9; ash B_Rutschhemmung: R9
Gipsfaserplatten 2-lagig (BSK) | WUN-H2-E02-007 | CEILING | layer 0.036 m | 1216Dfl0000046450/01 | m² | Trockenbauarbeiten | 1 | 0.036 | 0 | 1 | Deckenfläche |  | 0 | 0 | NEW | 2.5 | AllplanAttributes - Bezeichnung: Gipsfaserplatten 2-lagig (BSK); ash_lichte Raumhöhe: 2.5
 | WUN-H2-E02-007 | CEILING | Installationshöhe 0.714 m | 1216Dfl0000046450/02 | m² | Trockenbauarbeiten | 2 | 0.714 | 0 | 1 | Bekleidung | Installationshöhe | 0 | 0 | NEW | AllplanAttributes - OKFF: 0
 | WUN-H2-E02-007 | CEILING | A1 0.15 m | 1216Dfl0000046450/03 | m² | Trockenbauarbeiten | 3 | 0.15 | 0 | 1 | Bekleidung | A1 | 0 | 0 | NEW | Pset_CoveringCommon - AcousticRating: -; AllplanAttributes - OKFF: 0
 | WUN-H2-E02-007 | CEILING | D1 0.001 m | 1216Dfl0000046450/04 | m² | Maler- und Lackierarbeiten | 4 | 0.001 | 0 | 1 | Bekleidung | D1 | 0 | 0 | NEW | AllplanAttributes - OKFF: 0
Gipsfaserplatten 2-lagig (BSK) | WUN-H2-E02-007 | CEILING | layer 0.036 m | 1216Dfl0812844552/01 | m² | Trockenbauarbeiten | 1 | 0.036 | 0 | 1 | Deckenfläche |  | 0 | 0 | NEW | 2.5 | AllplanAttributes - Bezeichnung: Gipsfaserplatten 2-lagig (BSK); ash_lichte Raumhöhe: 2.5
 | WUN-H2-E02-007 | CEILING | Installationshöhe 0.714 m | 1216Dfl0812844552/02 | m² | Trockenbauarbeiten | 2 | 0.714 | 0 | 1 | Bekleidung | Installationshöhe | 0 | 0 | NEW | AllplanAttributes - OKFF: 0
 | WUN-H2-E02-007 | CEILING | Aa 0.15 m | 1216Dfl0812844552/03 | m² | Trockenbauarbeiten | 3 | 0.15 | 0 | 1 | Bekleidung | Aa | 0 | 0 | NEW | Pset_CoveringCommon - AcousticRating: -; AllplanAttributes - OKFF: 0
 | WUN-H2-E02-007 | CEILING | D1 0.001 m | 1216Dfl0812844552/04 | m² | Maler- und Lackierarbeiten | 4 | 0.001 | 0 | 1 | Bekleidung | D1 | 0 | 0 | NEW | AllplanAttributes - OKFF: 0
PVC Bahnenware Uni | WUN-H2-E02-001 | FLOORING | Ku2 0.15 m | 1216Bfl0000046720/01 | m² | Bodenbelagsarbeiten | 1 | 0.15 | 0 | 1 | Bodenfläche | Ku2 | 0 | 0 | NEW | AllplanAttributes - Bezeichnung: PVC Bahnenware Uni; Raumnr. Bauherr: 2.11_A2_02; ash B_Aufbau: B9; ash B_Rutschhemmung: R9
Gipsfaserplatten 2-lagig (BSK) | WUN-H2-E02-001 | CEILING | layer 0.036 m | 1216Dfl0000046721/01 | m² | Trockenbauarbeiten | 1 | 0.036 | 0 | 1 | Deckenfläche |  | 0 | 0 | NEW | 2.55 | AllplanAttributes - Bezeichnung: Gipsfaserplatten 2-lagig (BSK); ash_lichte Raumhöhe: 2.5
 | WUN-H2-E02-001 | CEILING | Installationshöhe 0.764 m | 1216Dfl0000046721/02 | m² | Trockenbauarbeiten | 2 | 0.764 | 0 | 1 | Bekleidung | Installationshöhe | 0 | 0 | NEW
 | WUN-H2-E02-001 | CEILING | A1 0.1 m | 1216Dfl0000046721/03 | m² | Trockenbauarbeiten | 3 | 0.1 | 0 | 1 | Bekleidung | A1 | 0 | 0 | NEW | Pset_CoveringCommon - AcousticRating: -
 | WUN-H2-E02-001 | CEILING | D1 0.001 m | 1216Dfl0000046721/04 | m² | Maler- und Lackierarbeiten | 4 | 0.001 | 0 | 1 | Bekleidung | D1 | 0 | 0 | NEW | AllplanAttributes - OKFF: 0
Gipsfaserplatten 2-lagig (BSK) | WUN-H2-E02-001 | CEILING | layer 0.036 m | 1216Dfl0812839171/01 | m² | Trockenbauarbeiten | 1 | 0.036 | 0 | 1 | Deckenfläche |  | 0 | 0 | NEW | 2.5 | AllplanAttributes - Bezeichnung: Gipsfaserplatten 2-lagig (BSK); ash_lichte Raumhöhe: 2.5
Gipsfaserplatten 2-lagig (BSK) | WUN-H2-E02-001 | CEILING | Installationshöhe 0.764 m | 1216Dfl0812839171/02 | m² | Trockenbauarbeiten | 2 | 0.764 | 0 | 1 | Bekleidung | Installationshöhe | 0 | 0 | NEW | AllplanAttributes - OKFF: 0
Rasterdecke | WUN-H2-E02-001 | CEILING | E3 0.1 m | 1216Dfl0812839171/03 | m² | Trockenbauarbeiten | 3 | 0.1 | 0 | 1 | Bekleidung | E3 | 0 | 0 | NEW | AllplanAttributes - Bezeichnung: Rasterdecke; OKFF: 0; Pset_CoveringCommon - AcousticRating: -
Fliesen | WUN-H2-E02-052 | FLOORING | Fl1 0.15 m | 1216Bfl0000046529/01 | m² | Bodenbelagsarbeiten | 1 | 0.15 | 0 | 1 | Bodenfläche | Fl1 | 0 | 0 | NEW | AllplanAttributes - Bezeichnung: Fliesen; Raumnr. Bauherr: 2.11_A2_02; ash B_Aufbau: B10; ash B_Rutschhemmung: R10
Gipsfaserplatten 2-lagig (BSK) | WUN-H2-E02-052 | CEILING | layer 0.036 m | 1216Dfl0000046528/01 | m² | Trockenbauarbeiten | 1 | 0.036 | 0 | 1 | Deckenfläche |  | 0 | 0 | NEW | 2.5 | AllplanAttributes - Bezeichnung: Gipsfaserplatten 2-lagig (BSK); ash_lichte Raumhöhe: 2.5
 | WUN-H2-E02-052 | CEILING | Installationshöhe 0.764 m | 1216Dfl0000046528/02 | m² | Trockenbauarbeiten | 2 | 0.764 | 0 | 1 | Bekleidung | Installationshöhe | 0 | 0 | NEW | AllplanAttributes - OKFF: 0
Gipskarton, imprägniert | WUN-H2-E02-052 | CEILING | B 0.1 m | 1216Dfl0000046528/03 | m² | Trockenbauarbeiten | 3 | 0.1 | 0 | 1 | Bekleidung | B | 0 | 0 | NEW | AllplanAttributes - Bezeichnung: Gipskarton, imprägniert; OKFF: 0; Pset_CoveringCommon - AcousticRating: -
 | WUN-H2-E02-052 | CEILING | D1 0.001 m | 1216Dfl0000046528/04 | m² | Maler- und Lackierarbeiten | 4 | 0.001 | 0 | 1 | Bekleidung | D1 | 0 | 0 | NEW | AllplanAttributes - OKFF: 0
Fliesen | WUN-H2-E02-052a | FLOORING | Fl1 0.15 m | 1216Bfl0000046552/01 | m² | Bodenbelagsarbeiten | 1 | 0.15 | 0 | 1 | Bodenfläche | Fl1 | 0 | 0 | NEW | AllplanAttributes - Bezeichnung: Fliesen; Raumnr. Bauherr: 2.11_A2_02; ash B_Aufbau: B10; ash B_Rutschhemmung: R10
Gipsfaserplatten 2-lagig (BSK) | WUN-H2-E02-052a | CEILING | layer 0.036 m | 1216Dfl0000046553/01 | m² | Trockenbauarbeiten | 1 | 0.036 | 0 | 1 | Deckenfläche |  | 0 | 0 | NEW | 2.5 | AllplanAttributes - Bezeichnung: Gipsfaserplatten 2-lagig (BSK); ash_lichte Raumhöhe: 2.5
 | WUN-H2-E02-052a | CEILING | Installationshöhe 0.764 m | 1216Dfl0000046553/02 | m² | Trockenbauarbeiten | 2 | 0.764 | 0 | 1 | Bekleidung | Installationshöhe | 0 | 0 | NEW | AllplanAttributes - OKFF: 0
Gipskarton, imprägniert | WUN-H2-E02-052a | CEILING | B 0.1 m | 1216Dfl0000046553/03 | m² | Trockenbauarbeiten | 3 | 0.1 | 0 | 1 | Bekleidung | B | 0 | 0 | NEW | AllplanAttributes - Bezeichnung: Gipskarton, imprägniert; OKFF: 0; Pset_CoveringCommon - AcousticRating: -
 | WUN-H2-E02-052a | CEILING | D1 0.001 m | 1216Dfl0000046553/04 | m² | Maler- und Lackierarbeiten | 4 | 0.001 | 0 | 1 | Bekleidung | D1 | 0 | 0 | NEW | AllplanAttributes - OKFF: 0
PVC Bahnenware Holzoptik | WUN-H2-E02-010 | FLOORING | Ku1 0.15 m | 1216Bfl0000046565/01 | m² | Bodenbelagsarbeiten | 1 | 0.15 | 0 | 1 | Bodenfläche | Ku1 | 0 | 0 | NEW | AllplanAttributes - Bezeichnung: PVC Bahnenware Holzoptik; Raumnr. Bauherr: 2.11_A2_02; ash B_Aufbau: B9; ash B_Rutschhemmung: R9
Gipsfaserplatten 2-lagig (BSK) | WUN-H2-E02-010 | CEILING | layer 0.036 m | 1216Dfl0000046576/01 | m² | Trockenbauarbeiten | 1 | 0.036 | 0 | 1 | Deckenfläche |  | 0 | 0 | NEW | 2.5 | AllplanAttributes - Bezeichnung: Gipsfaserplatten 2-lagig (BSK); ash_lichte Raumhöhe: 2.5
 | WUN-H2-E02-010 | CEILING | Installationshöhe 0.764 m | 1216Dfl0000046576/02 | m² | Trockenbauarbeiten | 2 | 0.764 | 0 | 1 | Bekleidung | Installationshöhe | 0 | 0 | NEW | AllplanAttributes - OKFF: 0
Kühldecke glatt | WUN-H2-E02-010 | CEILING | H7a 0.1 m | 1216Dfl0000046576/03 | m² | Trockenbauarbeiten | 3 | 0.1 | 0 | 1 | Bekleidung | H7a | 0 | 0 | NEW | AllplanAttributes - Bezeichnung: Kühldecke glatt; OKFF: 0; Pset_CoveringCommon - AcousticRating: -
 | WUN-H2-E02-010 | CEILING | D1 0.001 m | 1216Dfl0000046576/04 | m² | Maler- und Lackierarbeiten | 4 | 0.001 | 0 | 1 | Bekleidung | D1 | 0 | 0 | NEW | AllplanAttributes - OKFF: 0
Gipsfaserplatten 2-lagig (BSK) | WUN-H2-E02-010 | CEILING | layer 0.036 m | 1216Dfl0812998013/01 | m² | Trockenbauarbeiten | 1 | 0.036 | 0 | 1 | Deckenfläche |  | 0 | 0 | NEW | 2.5 | AllplanAttributes - Bezeichnung: Gipsfaserplatten 2-lagig (BSK); ash_lichte Raumhöhe: 2.5
 | WUN-H2-E02-010 | CEILING | Installationshöhe 0.764 m | 1216Dfl0812998013/02 | m² | Trockenbauarbeiten | 2 | 0.764 | 0 | 1 | Bekleidung | Installationshöhe | 0 | 0 | NEW | AllplanAttributes - OKFF: 0
Kühldecke gelocht | WUN-H2-E02-010 | CEILING | H7b 0.1 m | 1216Dfl0812998013/03 | m² | Trockenbauarbeiten | 3 | 0.1 | 0 | 1 | Bekleidung | H7b | 0 | 0 | NEW | AllplanAttributes - Bezeichnung: Kühldecke gelocht; OKFF: 0; Pset_CoveringCommon - AcousticRating: -
 | WUN-H2-E02-010 | CEILING | D1 0.001 m | 1216Dfl0812998013/04 | m² | Maler- und Lackierarbeiten | 4 | 0.001 | 0 | 1 | Bekleidung | D1 | 0 | 0 | NEW | AllplanAttributes - OKFF: 0
PVC Bahnenware Holzoptik | WUN-H2-E02-012 | FLOORING | Ku1 0.15 m | 1216Bfl0000046608/01 | m² | Bodenbelagsarbeiten | 1 | 0.15 | 0 | 1 | Bodenfläche | Ku1 | 0 | 0 | NEW | AllplanAttributes - Bezeichnung: PVC Bahnenware Holzoptik; Raumnr. Bauherr: 2.11_A2_02; ash B_Aufbau: B9; ash B_Rutschhemmung: R9
Gipsfaserplatten 2-lagig (BSK) | WUN-H2-E02-012 | CEILING | layer 0.036 m | 1216Dfl0000046607/01 | m² | Trockenbauarbeiten | 1 | 0.036 | 0 | 1 | Deckenfläche |  | 0 | 0 | NEW | 2.5 | AllplanAttributes - Bezeichnung: Gipsfaserplatten 2-lagig (BSK); ash_lichte Raumhöhe: 2.5
 | WUN-H2-E02-012 | CEILING | Installationshöhe 0.764 m | 1216Dfl0000046607/02 | m² | Trockenbauarbeiten | 2 | 0.764 | 0 | 1 | Bekleidung | Installationshöhe | 0 | 0 | NEW | AllplanAttributes - OKFF: 0
 | WUN-H2-E02-012 | CEILING | A1 0.1 m | 1216Dfl0000046607/03 | m² | Trockenbauarbeiten | 3 | 0.1 | 0 | 1 | Bekleidung | A1 | 0 | 0 | NEW | Pset_CoveringCommon - AcousticRating: -; AllplanAttributes - OKFF: 0
 | WUN-H2-E02-012 | CEILING | D1 0.001 m | 1216Dfl0000046607/04 | m² | Maler- und Lackierarbeiten | 4 | 0.001 | 0 | 1 | Bekleidung | D1 | 0 | 0 | NEW | AllplanAttributes - OKFF: 0
PVC Bahnenware Holzoptik | WUN-H2-E02-064 | FLOORING | Ku1 0.15 m | 1216Bfl0000046828/01 | m² | Bodenbelagsarbeiten | 1 | 0.15 | 0 | 1 | Bodenfläche | Ku1 | 0 | 0 | NEW | AllplanAttributes - Bezeichnung: PVC Bahnenware Holzoptik; Raumnr. Bauherr: 2.11_A2_02; ash B_Aufbau: B9; ash B_Rutschhemmung: R9
Gipsfaserplatten 2-lagig (BSK) | WUN-H2-E02-064 | CEILING | layer 0.036 m | 1216Dfl0000046827/01 | m² | Trockenbauarbeiten | 1 | 0.036 | 0 | 1 | Deckenfläche |  | 0 | 0 | NEW | 2.5 | AllplanAttributes - Bezeichnung: Gipsfaserplatten 2-lagig (BSK); ash_lichte Raumhöhe: 2.5
 | WUN-H2-E02-064 | CEILING | Installationshöhe 0.764 m | 1216Dfl0000046827/02 | m² | Trockenbauarbeiten | 2 | 0.764 | 0 | 1 | Bekleidung | Installationshöhe | 0 | 0 | NEW | AllplanAttributes - OKFF: 0
 | WUN-H2-E02-064 | CEILING | A1 0.1 m | 1216Dfl0000046827/03 | m² | Trockenbauarbeiten | 3 | 0.1 | 0 | 1 | Bekleidung | A1 | 0 | 0 | NEW | Pset_CoveringCommon - AcousticRating: -; AllplanAttributes - OKFF: 0
 | WUN-H2-E02-064 | CEILING | D1 0.001 m | 1216Dfl0000046827/04 | m² | Maler- und Lackierarbeiten | 4 | 0.001 | 0 | 1 | Bekleidung | D1 | 0 | 0 | NEW | AllplanAttributes - OKFF: 0
Fliesen | WUN-H2-E02-064b | FLOORING | Fl1 0.15 m | 1216Bfl0000046800/01 | m² | Bodenbelagsarbeiten | 1 | 0.15 | 0 | 1 | Bodenfläche | Fl1 | 0 | 0 | NEW | AllplanAttributes - Bezeichnung: Fliesen; Raumnr. Bauherr: 2.11_A2_02; ash B_Aufbau: B10; ash B_Rutschhemmung: R10
Gipsfaserplatten 2-lagig (BSK) | WUN-H2-E02-064b | CEILING | layer 0.036 m | 1216Dfl0000046801/01 | m² | Trockenbauarbeiten | 1 | 0.036 | 0 | 1 | Deckenfläche |  | 0 | 0 | NEW | 2.5 | AllplanAttributes - Bezeichnung: Gipsfaserplatten 2-lagig (BSK); ash_lichte Raumhöhe: 2.5
 | WUN-H2-E02-064b | CEILING | Installationshöhe 0.764 m | 1216Dfl0000046801/02 | m² | Trockenbauarbeiten | 2 | 0.764 | 0 | 1 | Bekleidung | Installationshöhe | 0 | 0 | NEW | AllplanAttributes - OKFF: 0
Gipskarton, imprägniert | WUN-H2-E02-064b | CEILING | B 0.1 m | 1216Dfl0000046801/03 | m² | Trockenbauarbeiten | 3 | 0.1 | 0 | 1 | Bekleidung | B | 0 | 0 | NEW | AllplanAttributes - Bezeichnung: Gipskarton, imprägniert; OKFF: 0; Pset_CoveringCommon - AcousticRating: -
 | WUN-H2-E02-064b | CEILING | D1 0.001 m | 1216Dfl0000046801/04 | m² | Maler- und Lackierarbeiten | 4 | 0.001 | 0 | 1 | Bekleidung | D1 | 0 | 0 | NEW | AllplanAttributes - OKFF: 0
Fliesen | WUN-H2-E02-012b | FLOORING | Fl1 0.15 m | 1216Bfl0000046669/01 | m² | Bodenbelagsarbeiten | 1 | 0.15 | 0 | 1 | Bodenfläche | Fl1 | 0 | 0 | NEW | AllplanAttributes - Bezeichnung: Fliesen; Raumnr. Bauherr: 2.11_A2_02; ash B_Aufbau: B10; ash B_Rutschhemmung: R10
Gipsfaserplatten 2-lagig (BSK) | WUN-H2-E02-012b | CEILING | layer 0.036 m | 1216Dfl0000046668/01 | m² | Trockenbauarbeiten | 1 | 0.036 | 0 | 1 | Deckenfläche |  | 0 | 0 | NEW | 2.5 | AllplanAttributes - Bezeichnung: Gipsfaserplatten 2-lagig (BSK); ash_lichte Raumhöhe: 2.5
Gipskarton, imprägniert | WUN-H2-E02-012b | CEILING | Installationshöhe 0.764 m | 1216Dfl0000046668/02 | m² | Trockenbauarbeiten | 2 | 0.764 | 0 | 1 | Bekleidung | Installationshöhe | 0 | 0 | NEW | AllplanAttributes - OKFF: 0
Gipskarton, imprägniert | WUN-H2-E02-012b | CEILING | B 0.1 m | 1216Dfl0000046668/03 | m² | Trockenbauarbeiten | 3 | 0.1 | 0 | 1 | Bekleidung | B | 0 | 0 | NEW | AllplanAttributes - Bezeichnung: Gipskarton, imprägniert; OKFF: 0; Pset_CoveringCommon - AcousticRating: -
Gipskarton, imprägniert | WUN-H2-E02-012b | CEILING | D1 0.001 m | 1216Dfl0000046668/04 | m² | Maler- und Lackierarbeiten | 4 | 0.001 | 0 | 1 | Bekleidung | D1 | 0 | 0 | NEW | AllplanAttributes - OKFF: 0
PVC Bahnenware Holzoptik | WUN-H2-E02-049 | FLOORING | Ku1 0.15 m | 1216Bfl0000046505/01 | m² | Bodenbelagsarbeiten | 1 | 0.15 | 0 | 1 | Bodenfläche | Ku1 | 0 | 0 | NEW | AllplanAttributes - Bezeichnung: PVC Bahnenware Holzoptik; Raumnr. Bauherr: 2.11_A2_02; ash B_Aufbau: B9; ash B_Rutschhemmung: R9
Gipsfaserplatten 2-lagig (BSK) | WUN-H2-E02-049 | CEILING | layer 0.036 m | 1216Dfl0000046504/01 | m² | Trockenbauarbeiten | 1 | 0.036 | 0 | 1 | Deckenfläche |  | 0 | 0 | NEW | 2.5 | AllplanAttributes - Bezeichnung: Gipsfaserplatten 2-lagig (BSK); ash_lichte Raumhöhe: 2.5
 | WUN-H2-E02-049 | CEILING | Installationshöhe 0.764 m | 1216Dfl0000046504/02 | m² | Trockenbauarbeiten | 2 | 0.764 | 0 | 1 | Bekleidung | Installationshöhe | 0 | 0 | NEW | AllplanAttributes - OKFF: 0
Gipskarton, imprägniert | WUN-H2-E02-049 | CEILING | B 0.1 m | 1216Dfl0000046504/03 | m² | Trockenbauarbeiten | 3 | 0.1 | 0 | 1 | Bekleidung | B | 0 | 0 | NEW | AllplanAttributes - Bezeichnung: Gipskarton, imprägniert; OKFF: 0; Pset_CoveringCommon - AcousticRating: -
 | WUN-H2-E02-049 | CEILING | D1 0.001 m | 1216Dfl0000046504/04 | m² | Maler- und Lackierarbeiten | 4 | 0.001 | 0 | 1 | Bekleidung | D1 | 0 | 0 | NEW | AllplanAttributes - OKFF: 0
Fliesen | WUN-H2-E02-052b | FLOORING | Fl1 0.15 m | 1216Bfl0000046540/01 | m² | Bodenbelagsarbeiten | 1 | 0.15 | 0 | 1 | Bodenfläche | Fl1 | 0 | 0 | NEW | AllplanAttributes - Bezeichnung: Fliesen; Raumnr. Bauherr: 2.11_A2_02; ash B_Aufbau: B10; ash B_Rutschhemmung: R10
Gipsfaserplatten 2-lagig (BSK) | WUN-H2-E02-052b | CEILING | layer 0.036 m | 1216Dfl0000046541/01 | m² | Trockenbauarbeiten | 1 | 0.036 | 0 | 1 | Deckenfläche |  | 0 | 0 | NEW | 2.5 | AllplanAttributes - Bezeichnung: Gipsfaserplatten 2-lagig (BSK); ash_lichte Raumhöhe: 2.5
Gipskarton, imprägniert | WUN-H2-E02-052b | CEILING | Installationshöhe 0.764 m | 1216Dfl0000046541/02 | m² | Trockenbauarbeiten | 2 | 0.764 | 0 | 1 | Bekleidung | Installationshöhe | 0 | 0 | NEW | AllplanAttributes - OKFF: 0
Gipskarton, imprägniert | WUN-H2-E02-052b | CEILING | B 0.1 m | 1216Dfl0000046541/03 | m² | Trockenbauarbeiten | 3 | 0.1 | 0 | 1 | Bekleidung | B | 0 | 0 | NEW | AllplanAttributes - Bezeichnung: Gipskarton, imprägniert; OKFF: 0; Pset_CoveringCommon - AcousticRating: -
Gipskarton, imprägniert | WUN-H2-E02-052b | CEILING | D1 0.001 m | 1216Dfl0000046541/04 | m² | Maler- und Lackierarbeiten | 4 | 0.001 | 0 | 1 | Bekleidung | D1 | 0 | 0 | NEW | AllplanAttributes - OKFF: 0
Fliesen | WUN-H2-E02-062 | FLOORING | Fl1 0.15 m | 1216Bfl0000046746/01 | m² | Bodenbelagsarbeiten | 1 | 0.15 | 0 | 1 | Bodenfläche | Fl1 | 0 | 0 | NEW | AllplanAttributes - Bezeichnung: Fliesen; Raumnr. Bauherr: 2.11_A2_02; ash B_Aufbau: B10; ash B_Rutschhemmung: R10
Gipsfaserplatten 2-lagig (BSK) | WUN-H2-E02-062 | CEILING | layer 0.036 m | 1216Dfl0000046747/01 | m² | Trockenbauarbeiten | 1 | 0.036 | 0 | 1 | Deckenfläche |  | 0 | 0 | NEW | 2.5 | AllplanAttributes - Bezeichnung: Gipsfaserplatten 2-lagig (BSK); ash_lichte Raumhöhe: 2.5
 | WUN-H2-E02-062 | CEILING | Installationshöhe 0.764 m | 1216Dfl0000046747/02 | m² | Trockenbauarbeiten | 2 | 0.764 | 0 | 1 | Bekleidung | Installationshöhe | 0 | 0 | NEW | AllplanAttributes - OKFF: 0
Gipskarton, imprägniert | WUN-H2-E02-062 | CEILING | B 0.1 m | 1216Dfl0000046747/03 | m² | Trockenbauarbeiten | 3 | 0.1 | 0 | 1 | Bekleidung | B | 0 | 0 | NEW | AllplanAttributes - Bezeichnung: Gipskarton, imprägniert; OKFF: 0; Pset_CoveringCommon - AcousticRating: -
 | WUN-H2-E02-062 | CEILING | D1 0.001 m | 1216Dfl0000046747/04 | m² | Maler- und Lackierarbeiten | 4 | 0.001 | 0 | 1 | Bekleidung | D1 | 0 | 0 | NEW | AllplanAttributes - OKFF: 0
PVC Bahnenware Holzoptik | WUN-H2-E02-F09a | FLOORING | Ku1 0.15 m | 1216Bfl0000047111/01 | m² | Bodenbelagsarbeiten | 1 | 0.15 | 0 | 1 | Bodenfläche | Ku1 | 0 | 0 | NEW | AllplanAttributes - Bezeichnung: PVC Bahnenware Holzoptik; Raumnr. Bauherr: 2.11_A2_02; ash B_Aufbau: B9; ash B_Rutschhemmung: R9
Gipsfaserplatten 2-lagig (BSK) | WUN-H2-E02-F09a | CEILING | layer 0.036 m | 1216Dfl0812862127/01 | m² | Trockenbauarbeiten | 1 | 0.036 | 0 | 1 | Deckenfläche |  | 0 | 0 | NEW | 2.5 | AllplanAttributes - Bezeichnung: Gipsfaserplatten 2-lagig (BSK); ash_lichte Raumhöhe: 2.5
 | WUN-H2-E02-F09a | CEILING | Installationshöhe 0.714 m | 1216Dfl0812862127/02 | m² | Trockenbauarbeiten | 2 | 0.714 | 0 | 1 | Bekleidung | Installationshöhe | 0 | 0 | NEW
 | WUN-H2-E02-F09a | CEILING | Aa 0.15 m | 1216Dfl0812862127/03 | m² | Trockenbauarbeiten | 3 | 0.15 | 0 | 1 | Bekleidung | Aa | 0 | 0 | NEW | Pset_CoveringCommon - AcousticRating: -
 | WUN-H2-E02-F09a | CEILING | D1 0.001 m | 1216Dfl0812862127/04 | m² | Maler- und Lackierarbeiten | 4 | 0.001 | 0 | 1 | Bekleidung | D1 | 0 | 0 | NEW
Gipsfaserplatten 2-lagig (BSK) | WUN-H2-E02-F09a | CEILING | layer 0.036 m | 1216Dfl0000047110/01 | m² | Trockenbauarbeiten | 1 | 0.036 | 0 | 1 | Deckenfläche |  | 0 | 0 | NEW | 2.5 | AllplanAttributes - Bezeichnung: Gipsfaserplatten 2-lagig (BSK); ash_lichte Raumhöhe: 2.5
 | WUN-H2-E02-F09a | CEILING | Installationshöhe 0.714 m | 1216Dfl0000047110/02 | m² | Trockenbauarbeiten | 2 | 0.714 | 0 | 1 | Bekleidung | Installationshöhe | 0 | 0 | NEW
 | WUN-H2-E02-F09a | CEILING | A1 0.15 m | 1216Dfl0000047110/03 | m² | Trockenbauarbeiten | 3 | 0.15 | 0 | 1 | Bekleidung | A1 | 0 | 0 | NEW | Pset_CoveringCommon - AcousticRating: -
 | WUN-H2-E02-F09a | CEILING | D1 0.001 m | 1216Dfl0000047110/04 | m² | Maler- und Lackierarbeiten | 4 | 0.001 | 0 | 1 | Bekleidung | D1 | 0 | 0 | NEW
PVC Bahnenware Holzoptik | WUN-H2-E02-F09b | FLOORING | Ku1 0.15 m | 1216Bfl0000046852/01 | m² | Bodenbelagsarbeiten | 1 | 0.15 | 0 | 1 | Bodenfläche | Ku1 | 0 | 0 | NEW | AllplanAttributes - Bezeichnung: PVC Bahnenware Holzoptik; Raumnr. Bauherr: 2.11_A2_02; ash B_Aufbau: B9; ash B_Rutschhemmung: R9
Gipsfaserplatten 2-lagig (BSK) | WUN-H2-E02-F09b | CEILING | layer 0.036 m | 1216Dfl0000046851/01 | m² | Trockenbauarbeiten | 1 | 0.036 | 0 | 1 | Deckenfläche |  | 0 | 0 | NEW | 2.5 | AllplanAttributes - Bezeichnung: Gipsfaserplatten 2-lagig (BSK); ash_lichte Raumhöhe: 2.5
 | WUN-H2-E02-F09b | CEILING | Installationshöhe 0.714 m | 1216Dfl0000046851/02 | m² | Trockenbauarbeiten | 2 | 0.714 | 0 | 1 | Bekleidung | Installationshöhe | 0 | 0 | NEW
 | WUN-H2-E02-F09b | CEILING | A1 0.15 m | 1216Dfl0000046851/03 | m² | Trockenbauarbeiten | 3 | 0.15 | 0 | 1 | Bekleidung | A1 | 0 | 0 | NEW | Pset_CoveringCommon - AcousticRating: -
 | WUN-H2-E02-F09b | CEILING | D1 0.001 m | 1216Dfl0000046851/04 | m² | Maler- und Lackierarbeiten | 4 | 0.001 | 0 | 1 | Bekleidung | D1 | 0 | 0 | NEW
Gipsfaserplatten 2-lagig (BSK) | WUN-H2-E02-F09b | CEILING | layer 0.036 m | 1216Dfl0812851578/01 | m² | Trockenbauarbeiten | 1 | 0.036 | 0 | 1 | Deckenfläche |  | 0 | 0 | NEW | 2.5 | AllplanAttributes - Bezeichnung: Gipsfaserplatten 2-lagig (BSK); ash_lichte Raumhöhe: 2.5
 | WUN-H2-E02-F09b | CEILING | Installationshöhe 0.714 m | 1216Dfl0812851578/02 | m² | Trockenbauarbeiten | 2 | 0.714 | 0 | 1 | Bekleidung | Installationshöhe | 0 | 0 | NEW | AllplanAttributes - OKFF: 0
 | WUN-H2-E02-F09b | CEILING | Aa 0.15 m | 1216Dfl0812851578/03 | m² | Trockenbauarbeiten | 3 | 0.15 | 0 | 1 | Bekleidung | Aa | 0 | 0 | NEW | Pset_CoveringCommon - AcousticRating: -; AllplanAttributes - OKFF: 0
 | WUN-H2-E02-F09b | CEILING | D1 0.001 m | 1216Dfl0812851578/04 | m² | Maler- und Lackierarbeiten | 4 | 0.001 | 0 | 1 | Bekleidung | D1 | 0 | 0 | NEW | AllplanAttributes - OKFF: 0
PVC Bahnenware Holzoptik | WUN-H2-E02-F03b | FLOORING | Ku1 0.15 m | 1216Bfl0000046593/01 | m² | Bodenbelagsarbeiten | 1 | 0.15 | 0 | 1 | Bodenfläche | Ku1 | 0 | 0 | NEW | AllplanAttributes - Bezeichnung: PVC Bahnenware Holzoptik; Raumnr. Bauherr: 2.11_A2_02; ash B_Aufbau: B9; ash B_Rutschhemmung: R9
Gipsfaserplatten 2-lagig (BSK) | WUN-H2-E02-F03b | CEILING | layer 0.036 m | 1216Dfl0000046592/01 | m² | Trockenbauarbeiten | 1 | 0.036 | 0 | 1 | Deckenfläche |  | 0 | 0 | NEW | 2.5 | AllplanAttributes - Bezeichnung: Gipsfaserplatten 2-lagig (BSK); ash_lichte Raumhöhe: 2.5
 | WUN-H2-E02-F03b | CEILING | Installationshöhe 0.714 m | 1216Dfl0000046592/02 | m² | Trockenbauarbeiten | 2 | 0.714 | 0 | 1 | Bekleidung | Installationshöhe | 0 | 0 | NEW
 | WUN-H2-E02-F03b | CEILING | A1 0.15 m | 1216Dfl0000046592/03 | m² | Trockenbauarbeiten | 3 | 0.15 | 0 | 1 | Bekleidung | A1 | 0 | 0 | NEW | Pset_CoveringCommon - AcousticRating: -
 | WUN-H2-E02-F03b | CEILING | D1 0.001 m | 1216Dfl0000046592/04 | m² | Maler- und Lackierarbeiten | 4 | 0.001 | 0 | 1 | Bekleidung | D1 | 0 | 0 | NEW
Gipsfaserplatten 2-lagig (BSK) | WUN-H2-E02-F03b | CEILING | layer 0.036 m | 1216Dfl0812848659/01 | m² | Trockenbauarbeiten | 1 | 0.036 | 0 | 1 | Deckenfläche |  | 0 | 0 | NEW | 2.5 | AllplanAttributes - Bezeichnung: Gipsfaserplatten 2-lagig (BSK); ash_lichte Raumhöhe: 2.5
 | WUN-H2-E02-F03b | CEILING | Installationshöhe 0.714 m | 1216Dfl0812848659/02 | m² | Trockenbauarbeiten | 2 | 0.714 | 0 | 1 | Bekleidung | Installationshöhe | 0 | 0 | NEW | AllplanAttributes - OKFF: 0
 | WUN-H2-E02-F03b | CEILING | Aa 0.15 m | 1216Dfl0812848659/03 | m² | Trockenbauarbeiten | 3 | 0.15 | 0 | 1 | Bekleidung | Aa | 0 | 0 | NEW | Pset_CoveringCommon - AcousticRating: -; AllplanAttributes - OKFF: 0
 | WUN-H2-E02-F03b | CEILING | D1 0.001 m | 1216Dfl0812848659/04 | m² | Maler- und Lackierarbeiten | 4 | 0.001 | 0 | 1 | Bekleidung | D1 | 0 | 0 | NEW | AllplanAttributes - OKFF: 0
PVC Bahnenware Holzoptik | WUN-H2-E02-F03a | FLOORING | Ku1 0.15 m | 1216Bfl0000046465/01 | m² | Bodenbelagsarbeiten | 1 | 0.15 | 0 | 1 | Bodenfläche | Ku1 | 0 | 0 | NEW | AllplanAttributes - Bezeichnung: PVC Bahnenware Holzoptik; Raumnr. Bauherr: 2.11_A2_02; ash B_Aufbau: B9; ash B_Rutschhemmung: R9
Gipsfaserplatten 2-lagig (BSK) | WUN-H2-E02-F03a | CEILING | layer 0.036 m | 1216Dfl0000046464/01 | m² | Trockenbauarbeiten | 1 | 0.036 | 0 | 1 | Deckenfläche |  | 0 | 0 | NEW | 2.5 | AllplanAttributes - Bezeichnung: Gipsfaserplatten 2-lagig (BSK); ash_lichte Raumhöhe: 2.5
 | WUN-H2-E02-F03a | CEILING | Installationshöhe 0.714 m | 1216Dfl0000046464/02 | m² | Trockenbauarbeiten | 2 | 0.714 | 0 | 1 | Bekleidung | Installationshöhe | 0 | 0 | NEW
 | WUN-H2-E02-F03a | CEILING | A1 0.15 m | 1216Dfl0000046464/03 | m² | Trockenbauarbeiten | 3 | 0.15 | 0 | 1 | Bekleidung | A1 | 0 | 0 | NEW | Pset_CoveringCommon - AcousticRating: -
 | WUN-H2-E02-F03a | CEILING | D1 0.001 m | 1216Dfl0000046464/04 | m² | Maler- und Lackierarbeiten | 4 | 0.001 | 0 | 1 | Bekleidung | D1 | 0 | 0 | NEW
Gipsfaserplatten 2-lagig (BSK) | WUN-H2-E02-F03a | CEILING | layer 0.036 m | 1216Dfl0812848079/01 | m² | Trockenbauarbeiten | 1 | 0.036 | 0 | 1 | Deckenfläche |  | 0 | 0 | NEW | 2.5 | AllplanAttributes - Bezeichnung: Gipsfaserplatten 2-lagig (BSK); ash_lichte Raumhöhe: 2.5
 | WUN-H2-E02-F03a | CEILING | Installationshöhe 0.714 m | 1216Dfl0812848079/02 | m² | Trockenbauarbeiten | 2 | 0.714 | 0 | 1 | Bekleidung | Installationshöhe | 0 | 0 | NEW | AllplanAttributes - OKFF: 0
 | WUN-H2-E02-F03a | CEILING | Aa 0.15 m | 1216Dfl0812848079/03 | m² | Trockenbauarbeiten | 3 | 0.15 | 0 | 1 | Bekleidung | Aa | 0 | 0 | NEW | Pset_CoveringCommon - AcousticRating: -; AllplanAttributes - OKFF: 0
 | WUN-H2-E02-F03a | CEILING | D1 0.001 m | 1216Dfl0812848079/04 | m² | Maler- und Lackierarbeiten | 4 | 0.001 | 0 | 1 | Bekleidung | D1 | 0 | 0 | NEW | AllplanAttributes - OKFF: 0
PVC Bahnenware Holzoptik | WUN-H2-E02-063 | FLOORING | Ku1 0.15 m | 1216Bfl0000046825/01 | m² | Bodenbelagsarbeiten | 1 | 0.15 | 0 | 1 | Bodenfläche | Ku1 | 0 | 0 | NEW | AllplanAttributes - Bezeichnung: PVC Bahnenware Holzoptik; Raumnr. Bauherr: 2.11_A2_02; ash B_Aufbau: B9; ash B_Rutschhemmung: R9
Gipsfaserplatten 2-lagig (BSK) | WUN-H2-E02-063 | CEILING | layer 0.036 m | 1216Dfl0812850998/01 | m² | Trockenbauarbeiten | 1 | 0.036 | 0 | 1 | Deckenfläche |  | 0 | 0 | NEW | 2.5 | AllplanAttributes - Bezeichnung: Gipsfaserplatten 2-lagig (BSK); ash_lichte Raumhöhe: 2.5
 | WUN-H2-E02-063 | CEILING | Installationshöhe 0.714 m | 1216Dfl0812850998/02 | m² | Trockenbauarbeiten | 2 | 0.714 | 0 | 1 | Bekleidung | Installationshöhe | 0 | 0 | NEW | AllplanAttributes - OKFF: 0
 | WUN-H2-E02-063 | CEILING | Aa 0.15 m | 1216Dfl0812850998/03 | m² | Trockenbauarbeiten | 3 | 0.15 | 0 | 1 | Bekleidung | Aa | 0 | 0 | NEW | Pset_CoveringCommon - AcousticRating: -; AllplanAttributes - OKFF: 0
 | WUN-H2-E02-063 | CEILING | D1 0.001 m | 1216Dfl0812850998/04 | m² | Maler- und Lackierarbeiten | 4 | 0.001 | 0 | 1 | Bekleidung | D1 | 0 | 0 | NEW | AllplanAttributes - OKFF: 0
Gipsfaserplatten 2-lagig (BSK) | WUN-H2-E02-063 | CEILING | layer 0.036 m | 1216Dfl0000046824/01 | m² | Trockenbauarbeiten | 1 | 0.036 | 0 | 1 | Deckenfläche |  | 0 | 0 | NEW | 2.5 | AllplanAttributes - Bezeichnung: Gipsfaserplatten 2-lagig (BSK); ash_lichte Raumhöhe: 2.5
 | WUN-H2-E02-063 | CEILING | Installationshöhe 0.714 m | 1216Dfl0000046824/02 | m² | Trockenbauarbeiten | 2 | 0.714 | 0 | 1 | Bekleidung | Installationshöhe | 0 | 0 | NEW | AllplanAttributes - OKFF: 0
 | WUN-H2-E02-063 | CEILING | A1 0.15 m | 1216Dfl0000046824/03 | m² | Trockenbauarbeiten | 3 | 0.15 | 0 | 1 | Bekleidung | A1 | 0 | 0 | NEW | Pset_CoveringCommon - AcousticRating: -; AllplanAttributes - OKFF: 0
 | WUN-H2-E02-063 | CEILING | D1 0.001 m | 1216Dfl0000046824/04 | m² | Maler- und Lackierarbeiten | 4 | 0.001 | 0 | 1 | Bekleidung | D1 | 0 | 0 | NEW | AllplanAttributes - OKFF: 0
PVC Bahnenware Holzoptik | WUN-H2-E02-013 | FLOORING | Ku1 0.15 m | 1216Bfl0000046620/01 | m² | Bodenbelagsarbeiten | 1 | 0.15 | 0 | 1 | Bodenfläche | Ku1 | 0 | 0 | NEW | AllplanAttributes - Bezeichnung: PVC Bahnenware Holzoptik; Raumnr. Bauherr: 2.11_A2_02; ash B_Aufbau: B9; ash B_Rutschhemmung: R9
Gipsfaserplatten 2-lagig (BSK) | WUN-H2-E02-013 | CEILING | layer 0.036 m | 1216Dfl0812993758/01 | m² | Trockenbauarbeiten | 1 | 0.036 | 0 | 1 | Deckenfläche |  | 0 | 0 | NEW | 2.5 | AllplanAttributes - Bezeichnung: Gipsfaserplatten 2-lagig (BSK); ash_lichte Raumhöhe: 2.5
 | WUN-H2-E02-013 | CEILING | Installationshöhe 0.714 m | 1216Dfl0812993758/02 | m² | Trockenbauarbeiten | 2 | 0.714 | 0 | 1 | Bekleidung | Installationshöhe | 0 | 0 | NEW | AllplanAttributes - OKFF: 0
 | WUN-H2-E02-013 | CEILING | Aa 0.15 m | 1216Dfl0812993758/03 | m² | Trockenbauarbeiten | 3 | 0.15 | 0 | 1 | Bekleidung | Aa | 0 | 0 | NEW | Pset_CoveringCommon - AcousticRating: -; AllplanAttributes - OKFF: 0
 | WUN-H2-E02-013 | CEILING | D1 0.001 m | 1216Dfl0812993758/04 | m² | Maler- und Lackierarbeiten | 4 | 0.001 | 0 | 1 | Bekleidung | D1 | 0 | 0 | NEW | AllplanAttributes - OKFF: 0
Gipsfaserplatten 2-lagig (BSK) | WUN-H2-E02-013 | CEILING | layer 0.036 m | 1216Dfl0812849239/01 | m² | Trockenbauarbeiten | 1 | 0.036 | 0 | 1 | Deckenfläche |  | 0 | 0 | NEW | 2.5 | AllplanAttributes - Bezeichnung: Gipsfaserplatten 2-lagig (BSK); ash_lichte Raumhöhe: 2.5
 | WUN-H2-E02-013 | CEILING | Installationshöhe 0.674 m | 1216Dfl0812849239/02 | m² | Trockenbauarbeiten | 2 | 0.674 | 0 | 1 | Bekleidung | Installationshöhe | 0 | 0 | NEW | AllplanAttributes - OKFF: 0
 | WUN-H2-E02-013 | CEILING | Aa 0.15 m | 1216Dfl0812849239/03 | m² | Trockenbauarbeiten | 3 | 0.15 | 0 | 1 | Bekleidung | Aa | 0 | 0 | NEW | Pset_CoveringCommon - AcousticRating: -; AllplanAttributes - OKFF: 0
 | WUN-H2-E02-013 | CEILING | D1 0.001 m | 1216Dfl0812849239/04 | m² | Maler- und Lackierarbeiten | 4 | 0.001 | 0 | 1 | Bekleidung | D1 | 0 | 0 | NEW | AllplanAttributes - OKFF: 0
PVC Bahnenware Holzoptik | WUN-H2-E02-009 | FLOORING | Ku1 0.15 m | 1216Bfl0000046517/01 | m² | Bodenbelagsarbeiten | 1 | 0.15 | 0 | 1 | Bodenfläche | Ku1 | 0 | 0 | NEW | AllplanAttributes - Bezeichnung: PVC Bahnenware Holzoptik; Raumnr. Bauherr: 2.11_A2_02; ash B_Aufbau: B9; ash B_Rutschhemmung: R9
Gipsfaserplatten 2-lagig (BSK) | WUN-H2-E02-009 | CEILING | layer 0.036 m | 1216Dfl0812997433/01 | m² | Trockenbauarbeiten | 1 | 0.036 | 0 | 1 | Deckenfläche |  | 0 | 0 | NEW | 2.5 | AllplanAttributes - Bezeichnung: Gipsfaserplatten 2-lagig (BSK); ash_lichte Raumhöhe: 2.5
Kühldecke glatt | WUN-H2-E02-009 | CEILING | Installationshöhe 0.764 m | 1216Dfl0812997433/02 | m² | Trockenbauarbeiten | 2 | 0.764 | 0 | 1 | Bekleidung | Installationshöhe | 0 | 0 | NEW | AllplanAttributes - OKFF: 0
Kühldecke glatt | WUN-H2-E02-009 | CEILING | H7a 0.1 m | 1216Dfl0812997433/03 | m² | Trockenbauarbeiten | 3 | 0.1 | 0 | 1 | Bekleidung | H7a | 0 | 0 | NEW | AllplanAttributes - Bezeichnung: Kühldecke glatt; OKFF: 0; Pset_CoveringCommon - AcousticRating: -
Kühldecke glatt | WUN-H2-E02-009 | CEILING | D1 0.001 m | 1216Dfl0812997433/04 | m² | Maler- und Lackierarbeiten | 4 | 0.001 | 0 | 1 | Bekleidung | D1 | 0 | 0 | NEW | AllplanAttributes - OKFF: 0
Gipsfaserplatten 2-lagig (BSK) | WUN-H2-E02-009 | CEILING | layer 0.036 m | 1216Dfl0000046516/01 | m² | Trockenbauarbeiten | 1 | 0.036 | 0 | 1 | Deckenfläche |  | 0 | 0 | NEW | 2.5 | AllplanAttributes - Bezeichnung: Gipsfaserplatten 2-lagig (BSK); ash_lichte Raumhöhe: 2.5
 | WUN-H2-E02-009 | CEILING | Installationshöhe 0.764 m | 1216Dfl0000046516/02 | m² | Trockenbauarbeiten | 2 | 0.764 | 0 | 1 | Bekleidung | Installationshöhe | 0 | 0 | NEW | AllplanAttributes - OKFF: 0
Kühldecke glatt | WUN-H2-E02-009 | CEILING | H7a 0.1 m | 1216Dfl0000046516/03 | m² | Trockenbauarbeiten | 3 | 0.1 | 0 | 1 | Bekleidung | H7a | 0 | 0 | NEW | AllplanAttributes - Bezeichnung: Kühldecke glatt; OKFF: 0; Pset_CoveringCommon - AcousticRating: -
 | WUN-H2-E02-009 | CEILING | D1 0.001 m | 1216Dfl0000046516/04 | m² | Maler- und Lackierarbeiten | 4 | 0.001 | 0 | 1 | Bekleidung | D1 | 0 | 0 | NEW | AllplanAttributes - OKFF: 0
PVC Bahnenware Holzoptik | WUN-H2-E02-067 | FLOORING | Ku1 0.15 m | 1216Bfl0000047161/01 | m² | Bodenbelagsarbeiten | 1 | 0.15 | 0 | 1 | Bodenfläche | Ku1 | 0 | 0 | NEW | AllplanAttributes - Bezeichnung: PVC Bahnenware Holzoptik; Raumnr. Bauherr: 2.11_A2_02; ash B_Aufbau: B9; ash B_Rutschhemmung: R9
Gipsfaserplatten 2-lagig (BSK) | WUN-H2-E02-067 | CEILING | layer 0.036 m | 1216Dfl0000047160/01 | m² | Trockenbauarbeiten | 1 | 0.036 | 0 | 1 | Deckenfläche |  | 0 | 0 | NEW | 2.5 | AllplanAttributes - Bezeichnung: Gipsfaserplatten 2-lagig (BSK); ash_lichte Raumhöhe: 2.5
 | WUN-H2-E02-067 | CEILING | Installationshöhe 0.764 m | 1216Dfl0000047160/02 | m² | Trockenbauarbeiten | 2 | 0.764 | 0 | 1 | Bekleidung | Installationshöhe | 0 | 0 | NEW | AllplanAttributes - OKFF: 0
Kühldecke glatt | WUN-H2-E02-067 | CEILING | H7a 0.1 m | 1216Dfl0000047160/03 | m² | Trockenbauarbeiten | 3 | 0.1 | 0 | 1 | Bekleidung | H7a | 0 | 0 | NEW | AllplanAttributes - Bezeichnung: Kühldecke glatt; OKFF: 0; Pset_CoveringCommon - AcousticRating: -
 | WUN-H2-E02-067 | CEILING | D1 0.001 m | 1216Dfl0000047160/04 | m² | Maler- und Lackierarbeiten | 4 | 0.001 | 0 | 1 | Bekleidung | D1 | 0 | 0 | NEW | AllplanAttributes - OKFF: 0
PVC Bahnenware Holzoptik | WUN-H2-E02-025 | FLOORING | Ku1 0.15 m | 1216Bfl0813170928/01 | m² | Bodenbelagsarbeiten | 1 | 0.15 | 0 | 1 | Bodenfläche | Ku1 | 0 | 0 | NEW | AllplanAttributes - Bezeichnung: PVC Bahnenware Holzoptik; Raumnr. Bauherr: 2.11_A2_02; ash B_Aufbau: B9; ash B_Rutschhemmung: R9
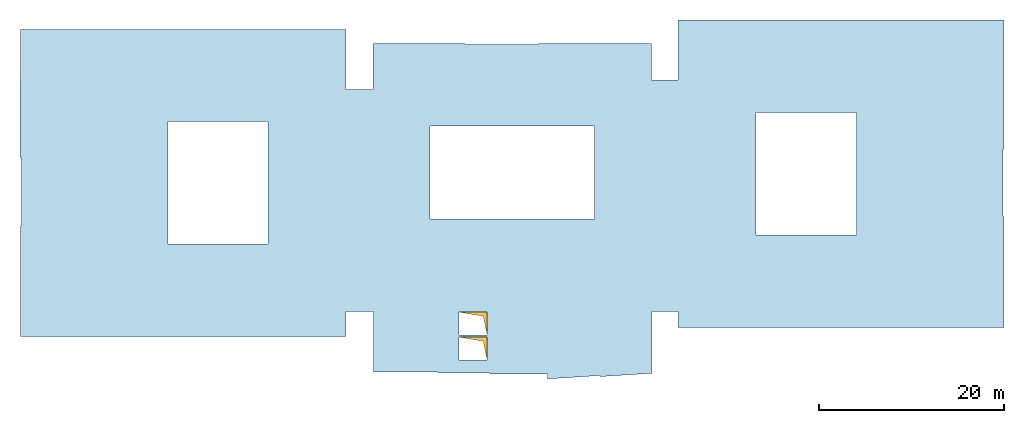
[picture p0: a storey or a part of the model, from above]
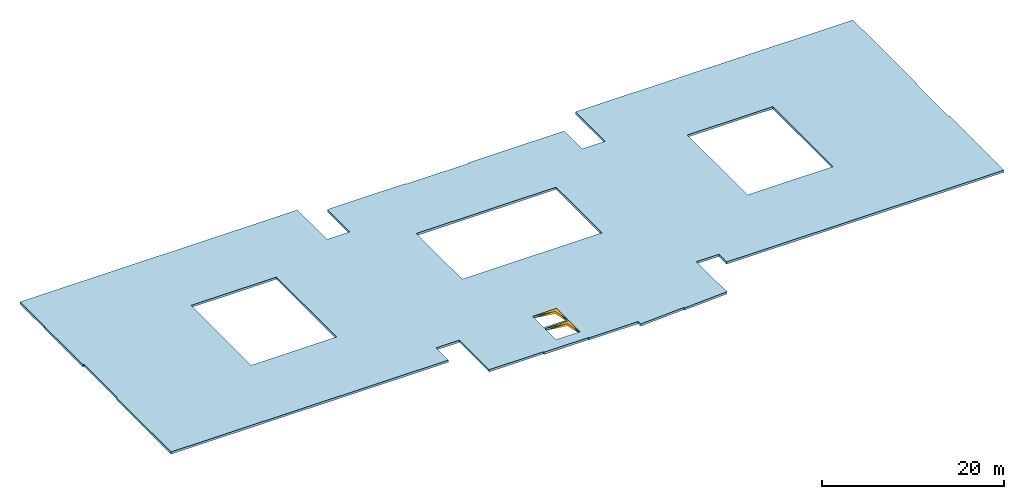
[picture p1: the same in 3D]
Properties of the parts of a building model (IFC4), part 10 of 80

# IfcCovering (3945)
Name | In | PredefinedType | Material | Allright_Bauteil_ID | Abrechnungsart | Gewerk | Schichtnummer | Schichtdicke (m) | Dicke (m) | Faktor | Objektname | AllplanAttributes, Material | Bezugshöhe | Deltahöhe | Status | D_lichte Raumhöhe [Zahl] (m)
Acrovyn | WUN-H2-E02-025 | CLADDING | 84 0.001 m | 1216Sfl0812842731/02 | m² | Maler- und Lackierarbeiten | 2 | 0.001 | 0 | 1 | Seitenfläche | 84 | 0 | 0 | NEW | AllplanAttributes - Bezeichnung: Acrovyn
Acrovyn | WUN-H2-E02-025 | CLADDING | 84 0.001 m | 1216Sfl0812842726/02 | m² | Maler- und Lackierarbeiten | 2 | 0.001 | 0 | 1 | Seitenfläche | 84 | 0 | 0 | NEW | AllplanAttributes - Bezeichnung: Acrovyn
Gipsfaserplatten 2-lagig (BSK) | WUN-H2-E02-025 | CEILING | layer 0.036 m | 1216Dfl0000046203/01 | m² | Trockenbauarbeiten | 1 | 0.036 | 0 | 1 | Deckenfläche |  | 0 | 0 | NEW | 3.15 | AllplanAttributes - Bezeichnung: Gipsfaserplatten 2-lagig (BSK); ash_lichte Raumhöhe: 3.47311
 | WUN-H2-E02-025 | CEILING | A1 0.1 m | 1216Dfl0000046214/01 | m² | Trockenbauarbeiten | 1 | 0.1 | 0 | 1 | Bekleidung | A1 | 0 | 0 | NEW | 2.5 | AllplanAttributes - ash_lichte Raumhöhe: 2.5; OKFF: 0; Pset_CoveringCommon - AcousticRating: -
 | WUN-H2-E02-025 | CEILING | D1 0.001 m | 1216Dfl0000046214/02 | m² | Maler- und Lackierarbeiten | 2 | 0.001 | 0 | 1 | Bekleidung | D1 | 0 | 0 | NEW | AllplanAttributes - OKFF: 0
 | WUN-H2-E02-025 | CEILING | A1 0.1 m | 1216Dfl0813301016/01 | m² | Trockenbauarbeiten | 1 | 0.1 | 0 | 1 | Bekleidung | A1 | 0 | 0 | NEW | 2.5 | AllplanAttributes - ash_lichte Raumhöhe: 3.150000; OKFF: 0; Pset_CoveringCommon - AcousticRating: -
 | WUN-H2-E02-025 | CEILING | D1 0.001 m | 1216Dfl0813301016/02 | m² | Maler- und Lackierarbeiten | 2 | 0.001 | 0 | 1 | Bekleidung | D1 | 0 | 0 | NEW | 2.5 | AllplanAttributes - ash_lichte Raumhöhe: 3.150000; OKFF: 0
PVC | WUN-H2-E02-S01 | FLOORING | Ku3 0.15 m | 1216Bfl0000046735/01 | m² | Bodenbelagsarbeiten | 1 | 0.15 | 0 | 1 | Bodenfläche | Ku3 | 0 | 0 | NEW | AllplanAttributes - Bezeichnung: PVC; Raumnr. Bauherr: 2.11_A2_02; ash B_Aufbau: B9; ash B_Rutschhemmung: R9
Gipsfaserplatten 2-lagig (BSK) | WUN-H2-E02-S01 | CEILING | C/C 0.036 m | 1216Dfl0000046734/01 | m² | Trockenbauarbeiten | 1 | 0.036 | 0 | 1 | Deckenfläche | C/C | 0 | 0 | NEW | 3.364 | AllplanAttributes - Bezeichnung: Gipsfaserplatten 2-lagig (BSK); ash_lichte Raumhöhe: 3.364
Gipsfaserplatten 2-lagig (BSK) | WUN-H2-E02-S01 | CEILING | D4 0.001 m | 1216Dfl0000046734/02 | m² | Maler- und Lackierarbeiten | 2 | 0.001 | 0 | 1 | Bekleidung | D4 | 0 | 0 | NEW
PVC | WUN-H2-E02-053 | FLOORING | Ku3 0.1 m | 1216Bfl0000047229/01 | m² | Bodenbelagsarbeiten | 1 | 0.1 | 0 | 1 | Bodenfläche | Ku3 | 0 | 0 | NEW | AllplanAttributes - Bezeichnung: PVC; Raumnr. Bauherr: 2.11_A2_02; ash B_Aufbau: B9; ash B_Rutschhemmung: R9
Gipsfaserplatten 2-lagig (BSK) | WUN-H2-E02-053 | CEILING | C/C 0.036 m | 1216Dfl0000047228/01 | m² | Trockenbauarbeiten | 1 | 0.036 | 0 | 1 | Deckenfläche | C/C | 0 | 0 | NEW | 3.364 | AllplanAttributes - Bezeichnung: Gipsfaserplatten 2-lagig (BSK); ash_lichte Raumhöhe: 3.364
Gipsfaserplatten 2-lagig (BSK) | WUN-H2-E02-053 | CEILING | D4 0.001 m | 1216Dfl0000047228/02 | m² | Maler- und Lackierarbeiten | 2 | 0.001 | 0 | 1 | Deckenfläche | D4 | 0 | 0 | NEW
PVC | WUN-H2-E02-054 | FLOORING | Ku3 0.1 m | 1216Bfl0000047241/01 | m² | Bodenbelagsarbeiten | 1 | 0.1 | 0 | 1 | Bodenfläche | Ku3 | 0 | 0 | NEW | AllplanAttributes - Bezeichnung: PVC; Raumnr. Bauherr: 2.11_A2_02; ash B_Aufbau: B9; ash B_Rutschhemmung: R9
Gipsfaserplatten 2-lagig (BSK) | WUN-H2-E02-054 | CEILING | C/C 0.036 m | 1216Dfl0000047240/01 | m² | Trockenbauarbeiten | 1 | 0.036 | 0 | 1 | Deckenfläche | C/C | 0 | 0 | NEW | 3.364 | AllplanAttributes - Bezeichnung: Gipsfaserplatten 2-lagig (BSK); ash_lichte Raumhöhe: 3.364
Gipsfaserplatten 2-lagig (BSK) | WUN-H2-E02-054 | CEILING | D4 0.001 m | 1216Dfl0000047240/02 | m² | Maler- und Lackierarbeiten | 2 | 0.001 | 0 | 1 | Deckenfläche | D4 | 0 | 0 | NEW
PVC | WUN-H2-E02-088 | FLOORING | Ku3 0.15 m | 1216Bfl0000047586/01 | m² | Bodenbelagsarbeiten | 1 | 0.15 | 0 | 1 | Bodenfläche | Ku3 | 0 | 0 | NEW | AllplanAttributes - Bezeichnung: PVC; Raumnr. Bauherr: 2.11_A2_02; ash B_Aufbau: B9; ash B_Rutschhemmung: R9
Gipsfaserplatten 2-lagig (BSK) | WUN-H2-E02-088 | CEILING | C/C 0.036 m | 1216Dfl0000047587/01 | m² | Trockenbauarbeiten | 1 | 0.036 | 0 | 1 | Deckenfläche | C/C | 0 | 0 | NEW | 3.364 | AllplanAttributes - Bezeichnung: Gipsfaserplatten 2-lagig (BSK); ash_lichte Raumhöhe: 3.6668
Gipsfaserplatten 2-lagig (BSK) | WUN-H2-E02-088 | CEILING | D4 0.001 m | 1216Dfl0000047587/02 | m² | Maler- und Lackierarbeiten | 2 | 0.001 | 0 | 1 | Deckenfläche | D4 | 0 | 0 | NEW
PVC | WUN-H2-E02-028 | FLOORING | Ku3 0.15 m | 1216Bfl0000046190/01 | m² | Bodenbelagsarbeiten | 1 | 0.15 | 0 | 1 | Bodenfläche | Ku3 | 0 | 0 | NEW | AllplanAttributes - Bezeichnung: PVC; Raumnr. Bauherr: 2.11_A2_02; ash B_Aufbau: B9; ash B_Rutschhemmung: R9
Gipsfaserplatten 2-lagig (BSK) | WUN-H2-E02-028 | CEILING | C/C 0.036 m | 1216Dfl0000046191/01 | m² | Trockenbauarbeiten | 1 | 0.036 | 0 | 1 | Deckenfläche | C/C | 0 | 0 | NEW | 3.364 | AllplanAttributes - Bezeichnung: Gipsfaserplatten 2-lagig (BSK); ash_lichte Raumhöhe: 3.86369
Gipsfaserplatten 2-lagig (BSK) | WUN-H2-E02-028 | CEILING | D4 0.001 m | 1216Dfl0000046191/02 | m² | Maler- und Lackierarbeiten | 2 | 0.001 | 0 | 1 | Deckenfläche | D4 | 0 | 0 | NEW
PVC | WUN-H2-E02-027 | FLOORING | Ku3 0.15 m | 1216Bfl0000046178/01 | m² | Bodenbelagsarbeiten | 1 | 0.15 | 0 | 1 | Bodenfläche | Ku3 | 0 | 0 | NEW | AllplanAttributes - Bezeichnung: PVC; Raumnr. Bauherr: 2.11_A2_02; ash B_Aufbau: B9; ash B_Rutschhemmung: R9
Gipsfaserplatten 2-lagig (BSK) | WUN-H2-E02-027 | CEILING | C/C 0.036 m | 1216Dfl0000046179/01 | m² | Trockenbauarbeiten | 1 | 0.036 | 0 | 1 | Deckenfläche | C/C | 0 | 0 | NEW | 3.364 | AllplanAttributes - Bezeichnung: Gipsfaserplatten 2-lagig (BSK); ash_lichte Raumhöhe: 3.6668
Gipsfaserplatten 2-lagig (BSK) | WUN-H2-E02-027 | CEILING | D4 0.001 m | 1216Dfl0000046179/02 | m² | Maler- und Lackierarbeiten | 2 | 0.001 | 0 | 1 | Deckenfläche | D4 | 0 | 0 | NEW
PVC | WUN-H2-E02-087 | FLOORING | Ku3 0.15 m | 1216Bfl0000047574/01 | m² | Bodenbelagsarbeiten | 1 | 0.15 | 0 | 1 | Bodenfläche | Ku3 | 0 | 0 | NEW | AllplanAttributes - Bezeichnung: PVC; Raumnr. Bauherr: 2.11_A2_02; ash B_Aufbau: B9; ash B_Rutschhemmung: R9
Gipsfaserplatten 2-lagig (BSK) | WUN-H2-E02-087 | CEILING | C/C 0.036 m | 1216Dfl0000047575/01 | m² | Trockenbauarbeiten | 1 | 0.036 | 0 | 1 | Deckenfläche | C/C | 0 | 0 | NEW | 3.364 | AllplanAttributes - Bezeichnung: Gipsfaserplatten 2-lagig (BSK); ash_lichte Raumhöhe: 3.86369
Gipsfaserplatten 2-lagig (BSK) | WUN-H2-E02-087 | CEILING | D4 0.001 m | 1216Dfl0000047575/02 | m² | Maler- und Lackierarbeiten | 2 | 0.001 | 0 | 1 | Deckenfläche | D4 | 0 | 0 | NEW
PVC Bahnenware Uni | WUN-H2-E02-002 | FLOORING | Ku2 0.15 m | 1216Bfl0000046708/01 | m² | Bodenbelagsarbeiten | 1 | 0.15 | 0 | 1 | Bodenfläche | Ku2 | 0 | 0 | NEW | AllplanAttributes - Bezeichnung: PVC Bahnenware Uni; Raumnr. Bauherr: 2.11_A2_02; ash B_Aufbau: B9; ash B_Rutschhemmung: R9
Gipsfaserplatten 2-lagig (BSK) | WUN-H2-E02-002 | CEILING | layer 0.036 m | 1216Dfl0000046709/01 | m² | Trockenbauarbeiten | 1 | 0.036 | 0 | 1 | Deckenfläche |  | 0 | 0 | NEW | 2.55 | AllplanAttributes - Bezeichnung: Gipsfaserplatten 2-lagig (BSK); ash_lichte Raumhöhe: 2.5
Gipsfaserplatten 2-lagig (BSK) | WUN-H2-E02-002 | CEILING | Installationshöhe 0.764 m | 1216Dfl0000046709/02 | m² | Trockenbauarbeiten | 2 | 0.764 | 0 | 1 | Bekleidung | Installationshöhe | 0 | 0 | NEW
Rasterdecke | WUN-H2-E02-002 | CEILING | E3 0.1 m | 1216Dfl0000046709/03 | m² | Trockenbauarbeiten | 3 | 0.1 | 0 | 1 | Bekleidung | E3 | 0 | 0 | NEW | AllplanAttributes - Bezeichnung: Rasterdecke; Pset_CoveringCommon - AcousticRating: -
a-sh Abschluss Abhangdecke | H2 Ebene +1 | CEILING |  | 1165HWa0000124348 | m² |  |  |  |  |  | Gesamtwand |  |  |  | NEW | AllplanAttributes - Bezeichnung: a-sh Abschluss Abhangdecke; Attributset-Objekt: Covering; Object Layer Attributes #1, 2D Interaktion: yes; Object Layer Attributes #1, Gewerk: Trockenbauarbeiten; Object Layer Attributes #1, Material: A; Object Layer Attributes #1, Attributset-Objekt: Covering; Object Layer Attributes #1, Allright_Bauteil_ID: 1165Wa 0000124349; Object Layer Attributes #1, Abrechnungsart: m²; Object Layer Attributes #1, Objektname: Wand; Pset_CoveringCommon - IsExternal: no; FireRating: -; ThermalTransmittance: 0 W/K/m2; Reference: Reference
a-sh Abschluss Abhangdecke | H2 Ebene +1 | CEILING |  | 1165HWa0000124357 | m² |  |  |  |  |  | Gesamtwand |  |  |  | NEW | AllplanAttributes - Bezeichnung: a-sh Abschluss Abhangdecke; Attributset-Objekt: Covering; Object Layer Attributes #1, 2D Interaktion: yes; Object Layer Attributes #1, Gewerk: Trockenbauarbeiten; Object Layer Attributes #1, Material: A; Object Layer Attributes #1, Attributset-Objekt: Covering; Object Layer Attributes #1, Allright_Bauteil_ID: 1165Wa 0000124358; Object Layer Attributes #1, Abrechnungsart: m²; Object Layer Attributes #1, Objektname: Wand; Pset_CoveringCommon - IsExternal: no; FireRating: -; ThermalTransmittance: 0 W/K/m2; Reference: Reference
a-sh Abschluss Abhangdecke | H2 Ebene +1 | CEILING |  | 1165HWa0000124362 | m² |  |  |  |  |  | Gesamtwand |  |  |  | NEW | AllplanAttributes - Bezeichnung: a-sh Abschluss Abhangdecke; Attributset-Objekt: Covering; Object Layer Attributes #1, 2D Interaktion: yes; Object Layer Attributes #1, Gewerk: Trockenbauarbeiten; Object Layer Attributes #1, Material: A; Object Layer Attributes #1, Attributset-Objekt: Covering; Object Layer Attributes #1, Allright_Bauteil_ID: 1165Wa 0000124363; Object Layer Attributes #1, Abrechnungsart: m²; Object Layer Attributes #1, Objektname: Wand; Pset_CoveringCommon - IsExternal: no; FireRating: -; ThermalTransmittance: 0 W/K/m2; Reference: Reference
a-sh Abschluss Abhangdecke | H2 Ebene +1 | CEILING |  | 1165HWa0000124367 | m² |  |  |  |  |  | Gesamtwand |  |  |  | NEW | AllplanAttributes - Bezeichnung: a-sh Abschluss Abhangdecke; Attributset-Objekt: Covering; Object Layer Attributes #1, 2D Interaktion: yes; Object Layer Attributes #1, Gewerk: Trockenbauarbeiten; Object Layer Attributes #1, Material: A; Object Layer Attributes #1, Attributset-Objekt: Covering; Object Layer Attributes #1, Allright_Bauteil_ID: 1165Wa 0000124368; Object Layer Attributes #1, Abrechnungsart: m²; Object Layer Attributes #1, Objektname: Wand; Pset_CoveringCommon - IsExternal: no; FireRating: -; ThermalTransmittance: 0 W/K/m2; Reference: Reference
a-sh Abschluss Abhangdecke | H2 Ebene +1 | CEILING |  | 1165HWa0000127717 | m² |  |  |  |  |  | Gesamtwand |  |  |  | NEW | AllplanAttributes - Bezeichnung: a-sh Abschluss Abhangdecke; Attributset-Objekt: Covering; Object Layer Attributes #1, 2D Interaktion: yes; Object Layer Attributes #1, Gewerk: Trockenbauarbeiten; Object Layer Attributes #1, Material: A; Object Layer Attributes #1, Attributset-Objekt: Covering; Object Layer Attributes #1, Allright_Bauteil_ID: 1165Wa 0000127718; Object Layer Attributes #1, Abrechnungsart: m²; Object Layer Attributes #1, Objektname: Wand; Pset_CoveringCommon - IsExternal: no; FireRating: -; ThermalTransmittance: 0 W/K/m2; Reference: Reference
a-sh Abschluss Abhangdecke | H2 Ebene +1 | CEILING |  | 1165HWa0000127722 | m² |  |  |  |  |  | Gesamtwand |  |  |  | NEW | AllplanAttributes - Bezeichnung: a-sh Abschluss Abhangdecke; Attributset-Objekt: Covering; Object Layer Attributes #1, 2D Interaktion: yes; Object Layer Attributes #1, Gewerk: Trockenbauarbeiten; Object Layer Attributes #1, Material: A; Object Layer Attributes #1, Attributset-Objekt: Covering; Object Layer Attributes #1, Allright_Bauteil_ID: 1165Wa 0000127723; Object Layer Attributes #1, Abrechnungsart: m²; Object Layer Attributes #1, Objektname: Wand; Pset_CoveringCommon - IsExternal: no; FireRating: -; ThermalTransmittance: 0 W/K/m2; Reference: Reference
a-sh Abschluss Abhangdecke | H2 Ebene +1 | CEILING |  | 1165HWa0000129820 | m² |  |  |  |  |  | Gesamtwand |  |  |  | NEW | AllplanAttributes - Bezeichnung: a-sh Abschluss Abhangdecke; Attributset-Objekt: Covering; Object Layer Attributes #1, 2D Interaktion: yes; Object Layer Attributes #1, Gewerk: Trockenbauarbeiten; Object Layer Attributes #1, Material: A; Object Layer Attributes #1, Attributset-Objekt: Covering; Object Layer Attributes #1, Allright_Bauteil_ID: 1165Wa 0000129821; Object Layer Attributes #1, Abrechnungsart: m²; Object Layer Attributes #1, Objektname: Wand; Pset_CoveringCommon - IsExternal: no; FireRating: -; ThermalTransmittance: 0 W/K/m2; Reference: Reference
a-sh Abschluss Abhangdecke | H2 Ebene +1 | CEILING |  | 1165HWa0000129825 | m² |  |  |  |  |  | Gesamtwand |  |  |  | NEW | AllplanAttributes - Bezeichnung: a-sh Abschluss Abhangdecke; Attributset-Objekt: Covering; Object Layer Attributes #1, 2D Interaktion: yes; Object Layer Attributes #1, Gewerk: Trockenbauarbeiten; Object Layer Attributes #1, Material: A; Object Layer Attributes #1, Attributset-Objekt: Covering; Object Layer Attributes #1, Allright_Bauteil_ID: 1165Wa 0000129826; Object Layer Attributes #1, Abrechnungsart: m²; Object Layer Attributes #1, Objektname: Wand; Pset_CoveringCommon - IsExternal: no; FireRating: -; ThermalTransmittance: 0 W/K/m2; Reference: Reference
a-sh Abschluss Abhangdecke | H2 Ebene +1 | CEILING |  | 1165HWa0000129835 | m² |  |  |  |  |  | Gesamtwand |  |  |  | NEW | AllplanAttributes - Bezeichnung: a-sh Abschluss Abhangdecke; Attributset-Objekt: Covering; Object Layer Attributes #1, 2D Interaktion: yes; Object Layer Attributes #1, Gewerk: Trockenbauarbeiten; Object Layer Attributes #1, Material: A; Object Layer Attributes #1, Attributset-Objekt: Covering; Object Layer Attributes #1, Allright_Bauteil_ID: 1165Wa 0000129836; Object Layer Attributes #1, Abrechnungsart: m²; Object Layer Attributes #1, Objektname: Wand; Pset_CoveringCommon - IsExternal: no; FireRating: -; ThermalTransmittance: 0 W/K/m2; Reference: Reference
a-sh Abschluss Abhangdecke | H2 Ebene +1 | CEILING |  | 1165HWa0000129840 | m² |  |  |  |  |  | Gesamtwand |  |  |  | NEW | AllplanAttributes - Bezeichnung: a-sh Abschluss Abhangdecke; Attributset-Objekt: Covering; Object Layer Attributes #1, 2D Interaktion: yes; Object Layer Attributes #1, Gewerk: Trockenbauarbeiten; Object Layer Attributes #1, Material: A; Object Layer Attributes #1, Attributset-Objekt: Covering; Object Layer Attributes #1, Allright_Bauteil_ID: 1165Wa 0000129841; Object Layer Attributes #1, Abrechnungsart: m²; Object Layer Attributes #1, Objektname: Wand; Pset_CoveringCommon - IsExternal: no; FireRating: -; ThermalTransmittance: 0 W/K/m2; Reference: Reference
a-sh Abschluss Abhangdecke | H2 Ebene +1 | CEILING |  | 1165HWa0000129853 | m² |  |  |  |  |  | Gesamtwand |  |  |  | NEW | AllplanAttributes - Bezeichnung: a-sh Abschluss Abhangdecke; Attributset-Objekt: Covering; Object Layer Attributes #1, 2D Interaktion: yes; Object Layer Attributes #1, Gewerk: Trockenbauarbeiten; Object Layer Attributes #1, Material: A; Object Layer Attributes #1, Attributset-Objekt: Covering; Object Layer Attributes #1, Allright_Bauteil_ID: 1165Wa 0000129854; Object Layer Attributes #1, Abrechnungsart: m²; Object Layer Attributes #1, Objektname: Wand; Pset_CoveringCommon - IsExternal: no; FireRating: -; ThermalTransmittance: 0 W/K/m2; Reference: Reference
a-sh Abschluss Abhangdecke | H2 Ebene +1 | CEILING |  | 1165HWa0000129862 | m² |  |  |  |  |  | Gesamtwand |  |  |  | NEW | AllplanAttributes - Bezeichnung: a-sh Abschluss Abhangdecke; Attributset-Objekt: Covering; Object Layer Attributes #1, 2D Interaktion: yes; Object Layer Attributes #1, Gewerk: Trockenbauarbeiten; Object Layer Attributes #1, Material: A; Object Layer Attributes #1, Attributset-Objekt: Covering; Object Layer Attributes #1, Allright_Bauteil_ID: 1165Wa 0000129863; Object Layer Attributes #1, Abrechnungsart: m²; Object Layer Attributes #1, Objektname: Wand; Pset_CoveringCommon - IsExternal: no; FireRating: -; ThermalTransmittance: 0 W/K/m2; Reference: Reference
a-sh Abschluss Abhangdecke | H2 Ebene +1 | CEILING |  | 1165HWa0000129873 | m² |  |  |  |  |  | Gesamtwand |  |  |  | NEW | AllplanAttributes - Bezeichnung: a-sh Abschluss Abhangdecke; Attributset-Objekt: Covering; Object Layer Attributes #1, 2D Interaktion: yes; Object Layer Attributes #1, Gewerk: Trockenbauarbeiten; Object Layer Attributes #1, Material: A; Object Layer Attributes #1, Attributset-Objekt: Covering; Object Layer Attributes #1, Allright_Bauteil_ID: 1165Wa 0000129874; Object Layer Attributes #1, Abrechnungsart: m²; Object Layer Attributes #1, Objektname: Wand; Pset_CoveringCommon - IsExternal: no; FireRating: -; ThermalTransmittance: 0 W/K/m2; Reference: Reference
a-sh Abschluss Abhangdecke | H2 Ebene +1 | CEILING |  | 1165HWa0000129885 | m² |  |  |  |  |  | Gesamtwand |  |  |  | NEW | AllplanAttributes - Bezeichnung: a-sh Abschluss Abhangdecke; Attributset-Objekt: Covering; Object Layer Attributes #1, 2D Interaktion: yes; Object Layer Attributes #1, Gewerk: Trockenbauarbeiten; Object Layer Attributes #1, Material: A; Object Layer Attributes #1, Attributset-Objekt: Covering; Object Layer Attributes #1, Allright_Bauteil_ID: 1165Wa 0000129886; Object Layer Attributes #1, Abrechnungsart: m²; Object Layer Attributes #1, Objektname: Wand; Pset_CoveringCommon - IsExternal: no; FireRating: -; ThermalTransmittance: 0 W/K/m2; Reference: Reference
a-sh Abschluss Abhangdecke | H2 Ebene +1 | CEILING |  | 1165HWa0000129918 | m² |  |  |  |  |  | Gesamtwand |  |  |  | NEW | AllplanAttributes - Bezeichnung: a-sh Abschluss Abhangdecke; Attributset-Objekt: Covering; Object Layer Attributes #1, 2D Interaktion: yes; Object Layer Attributes #1, Gewerk: Trockenbauarbeiten; Object Layer Attributes #1, Material: A; Object Layer Attributes #1, Attributset-Objekt: Covering; Object Layer Attributes #1, Allright_Bauteil_ID: 1165Wa 0000129919; Object Layer Attributes #1, Abrechnungsart: m²; Object Layer Attributes #1, Objektname: Wand; Pset_CoveringCommon - IsExternal: no; FireRating: -; ThermalTransmittance: 0 W/K/m2; Reference: Reference
a-sh Abschluss Abhangdecke | H2 Ebene +1 | CEILING |  | 1165HWa0000129923 | m² |  |  |  |  |  | Gesamtwand |  |  |  | NEW | AllplanAttributes - Bezeichnung: a-sh Abschluss Abhangdecke; Attributset-Objekt: Covering; Object Layer Attributes #1, 2D Interaktion: yes; Object Layer Attributes #1, Gewerk: Trockenbauarbeiten; Object Layer Attributes #1, Material: A; Object Layer Attributes #1, Attributset-Objekt: Covering; Object Layer Attributes #1, Allright_Bauteil_ID: 1165Wa 0000129924; Object Layer Attributes #1, Abrechnungsart: m²; Object Layer Attributes #1, Objektname: Wand; Pset_CoveringCommon - IsExternal: no; FireRating: -; ThermalTransmittance: 0 W/K/m2; Reference: Reference
Gipsfaserplatten 2-lagig (BSK) | H2 Ebene +1 | CEILING | layer 0.036 m | 1165Dfl0000073548/01 | m² | Trockenbauarbeiten | 1 | 0.036 | 0 | 1 | Deckenfläche |  | 0 | 0 | NEW | 2.5 | AllplanAttributes - Bezeichnung: Gipsfaserplatten 2-lagig (BSK); RoomName: Flur
Gipsfaserplatten 2-lagig (BSK) | H2 Ebene +1 | CEILING | Installationshöhe 0.714 m | 1165Dfl0000073548/02 | m² | Trockenbauarbeiten | 2 | 0.714 | 0 | 1 | Bekleidung | Installationshöhe | 0 | 0 | NEW | 2.5 | AllplanAttributes - ash_lichte Raumhöhe: 2.500000; RoomName: Flur
Gipsfaserplatten 2-lagig (BSK) | H2 Ebene +1 | CEILING | A1 0.15 m | 1165Dfl0000073548/03 | m² | Trockenbauarbeiten | 3 | 0.15 | 0 | 1 | Bekleidung | A1 | 0 | 0 | NEW | 2.5 | AllplanAttributes - ash_lichte Raumhöhe: 2.500000; RoomName: Flur; Pset_CoveringCommon - AcousticRating: -
Gipsfaserplatten 2-lagig (BSK) | H2 Ebene +1 | CEILING | D1 0.001 m | 1165Dfl0000073548/04 | m² | Maler- und Lackierarbeiten | 4 | 0.001 | 0 | 1 | Bekleidung | D1 | 0 | 0 | NEW | 2.5 | AllplanAttributes - ash_lichte Raumhöhe: 2.500000; RoomName: Flur
Fliesen Großformat | WUN-H2-E01-T04 | FLOORING | Fl12 0.06 m | 1165Bfl0000087329/01 | m² | Bodenbelagsarbeiten | 1 | 0.06 | 0 | 1 | Bodenfläche | Fl12 | 0 | 0 | NEW | AllplanAttributes - Bezeichnung: Fliesen Großformat; Raumnr. Bauherr: 2.11_A2_02; ash B_Aufbau: B6; ash B_Rutschhemmung: R10
Fliesen Großformat | WUN-H2-E01-T04 | FLOORING | Fl12 0.1 m | 1165Bfl0000086955/01 | m² | Bodenbelagsarbeiten | 1 | 0.1 | 0 | 1 | Bodenfläche | Fl12 | 0 | 0 | NEW | AllplanAttributes - Bezeichnung: Fliesen Großformat; Raumnr. Bauherr: 2.11_A2_02; ash B_Aufbau: B7; ash B_Rutschhemmung: R10
Sichtbetonklasse SB3 | WUN-H2-E01-T04 | CLADDING | 03 0.001 m | 1165Sfl0000097229/02 | m² | Putz- und Stuckarbeiten | 2 | 0.001 | 0 | 1 | Seitenfläche | 03 | 0 | 0 | NEW | AllplanAttributes - Bezeichnung: Sichtbetonklasse SB3
Sichtbetonklasse SB3 | WUN-H2-E01-T04 | CLADDING | 47 0.001 m | 1165Sfl0000097229/04 | m² | Maler- und Lackierarbeiten | 4 | 0.001 | 0 | 1 | Seitenfläche | 47 | 0 | 0 | NEW
Gipsfaserplatten 2-lagig (BSK) | WUN-H2-E01-T04 | CEILING | layer 0.036 m | 1165Dfl0000028491/01 | m² | Trockenbauarbeiten | 1 | 0.036 | 0 | 1 | Deckenfläche |  | 0 | 0 | NEW | 3.1 | AllplanAttributes - Bezeichnung: Gipsfaserplatten 2-lagig (BSK); RoomName: TH 4
Gipsfaserplatten 2-lagig (BSK) | WUN-H2-E01-T04 | CEILING | Installationshöhe 0.164 m | 1165Dfl0000028491/02 | m² | Trockenbauarbeiten | 2 | 0.164 | 0 | 1 | Bekleidung | Installationshöhe | 0 | 0 | NEW | 3.1 | AllplanAttributes - ash_lichte Raumhöhe: 3.100000; RoomName: TH 4
Gipsfaserplatten 2-lagig (BSK) | WUN-H2-E01-T04 | CEILING | A1 0.1 m | 1165Dfl0000028491/03 | m² | Trockenbauarbeiten | 3 | 0.1 | 0 | 1 | Bekleidung | A1 | 0 | 0 | NEW | 3.1 | Pset_CoveringCommon - FireRating: F60; AcousticRating: -; AllplanAttributes - ash_lichte Raumhöhe: 3.100000; RoomName: TH 4
Gipsfaserplatten 2-lagig (BSK) | WUN-H2-E01-T04 | CEILING | D1 0.001 m | 1165Dfl0000028491/04 | m² | Maler- und Lackierarbeiten | 4 | 0.001 | 0 | 1 | Bekleidung | D1 | 0 | 0 | NEW | 3.1 | AllplanAttributes - ash_lichte Raumhöhe: 3.100000; RoomName: TH 4
Handlauf | WUN-H2-E01-T01 | CLADDING | 97 0.001 m | 1165Sfl0000055888/02 | m² | Maler- und Lackierarbeiten | 2 | 0.001 | 0 | 1 | Seitenfläche | 97 | 0 | 0 | NEW | AllplanAttributes - Bezeichnung: Handlauf
Fliesen Großformat | WUN-H2-E01-T01 | FLOORING | Fl12 0.06 m | 1165Bfl0000087697/01 | m² | Bodenbelagsarbeiten | 1 | 0.06 | 0 | 1 | Bodenfläche | Fl12 | 0 | 0 | NEW | AllplanAttributes - Bezeichnung: Fliesen Großformat; Raumnr. Bauherr: 2.11_A2_02; ash B_Aufbau: B6; ash B_Rutschhemmung: R10
Fliesen Großformat | WUN-H2-E01-T01 | FLOORING | Fl12 0.15 m | 1165Bfl0000088049/01 | m² | Bodenbelagsarbeiten | 1 | 0.15 | 0 | 1 | Bodenfläche | Fl12 | 0 | 0 | NEW | AllplanAttributes - Bezeichnung: Fliesen Großformat; Raumnr. Bauherr: 2.11_A2_02; ash B_Aufbau: B8; ash B_Rutschhemmung: R10
Sichtbetonklasse SB3 | WUN-H2-E01-T01 | CLADDING | 03 0.001 m | 1165Sfl0000096310/02 | m² | Putz- und Stuckarbeiten | 2 | 0.001 | 0 | 1 | Seitenfläche | 03 | 0 | 0 | NEW | AllplanAttributes - Bezeichnung: Sichtbetonklasse SB3
Sichtbetonklasse SB3 | WUN-H2-E01-T01 | CLADDING | 47 0.001 m | 1165Sfl0000096310/04 | m² | Maler- und Lackierarbeiten | 4 | 0.001 | 0 | 1 | Seitenfläche | 47 | 0 | 0 | NEW
Gipsfaserplatten 2-lagig (BSK) | WUN-H2-E01-T01 | CEILING | layer 0.036 m | 1165Dfl0000085009/01 | m² | Trockenbauarbeiten | 1 | 0.036 | 0 | 1 | Deckenfläche |  | 0 | 0 | NEW | 2.75 | AllplanAttributes - Bezeichnung: Gipsfaserplatten 2-lagig (BSK); RoomName: TH 1
Gipsfaserplatten 2-lagig (BSK) | WUN-H2-E01-T01 | CEILING | Installationshöhe 0.414 m | 1165Dfl0000085009/02 | m² | Trockenbauarbeiten | 2 | 0.414 | 0 | 1 | Bekleidung | Installationshöhe | 0 | 0 | NEW | 2.75 | AllplanAttributes - ash_lichte Raumhöhe: 2.750000; RoomName: TH 1
Gipsfaserplatten 2-lagig (BSK) | WUN-H2-E01-T01 | CEILING | Aa 0.2 m | 1165Dfl0000085009/03 | m² | Trockenbauarbeiten | 3 | 0.2 | 0 | 1 | Bekleidung | Aa | 0 | 0 | NEW | 2.75 | Pset_CoveringCommon - FireRating: F60; AcousticRating: -; AllplanAttributes - ash_lichte Raumhöhe: 2.750000; RoomName: TH 1
Gipsfaserplatten 2-lagig (BSK) | WUN-H2-E01-T01 | CEILING | D1 0.001 m | 1165Dfl0000085009/04 | m² | Maler- und Lackierarbeiten | 4 | 0.001 | 0 | 1 | Bekleidung | D1 | 0 | 0 | NEW | 2.75 | AllplanAttributes - ash_lichte Raumhöhe: 2.750000; RoomName: TH 1
Gipsfaserplatten 2-lagig (BSK) | WUN-H2-E01-T01 | CEILING | layer 0.036 m | 1165Dfl0000084855/01 | m² | Trockenbauarbeiten | 1 | 0.036 | 0 | 1 | Deckenfläche |  | 0 | 0 | NEW | 2.75 | AllplanAttributes - Bezeichnung: Gipsfaserplatten 2-lagig (BSK); RoomName: TH 1
Gipsfaserplatten 2-lagig (BSK) | WUN-H2-E01-T01 | CEILING | Installationshöhe 0.414 m | 1165Dfl0000084855/02 | m² | Trockenbauarbeiten | 2 | 0.414 | 0 | 1 | Bekleidung | Installationshöhe | 0 | 0 | NEW | 2.75 | AllplanAttributes - ash_lichte Raumhöhe: 2.750000; RoomName: TH 1
Gipsfaserplatten 2-lagig (BSK) | WUN-H2-E01-T01 | CEILING | A1 0.2 m | 1165Dfl0000084855/03 | m² | Trockenbauarbeiten | 3 | 0.2 | 0 | 1 | Bekleidung | A1 | 0 | 0 | NEW | 2.75 | Pset_CoveringCommon - FireRating: F60; AcousticRating: -; AllplanAttributes - ash_lichte Raumhöhe: 2.750000; RoomName: TH 1
Gipsfaserplatten 2-lagig (BSK) | WUN-H2-E01-T01 | CEILING | D1 0.001 m | 1165Dfl0000084855/04 | m² | Maler- und Lackierarbeiten | 4 | 0.001 | 0 | 1 | Bekleidung | D1 | 0 | 0 | NEW | 2.75 | AllplanAttributes - ash_lichte Raumhöhe: 2.750000; RoomName: TH 1
Gipsfaserplatten 2-lagig (BSK) | WUN-H2-E01-T01 | CEILING | layer 0.036 m | 1165Dfl0000085001/01 | m² | Trockenbauarbeiten | 1 | 0.036 | 0 | 1 | Deckenfläche |  | 0 | 0 | NEW | 3.1 | AllplanAttributes - Bezeichnung: Gipsfaserplatten 2-lagig (BSK); RoomName: TH 1
Gipsfaserplatten 2-lagig (BSK) | WUN-H2-E01-T01 | CEILING | Installationshöhe 0.164 m | 1165Dfl0000085001/02 | m² | Trockenbauarbeiten | 2 | 0.164 | 0 | 1 | Bekleidung | Installationshöhe | 0 | 0 | NEW | 3.1 | AllplanAttributes - ash_lichte Raumhöhe: 3.100000; RoomName: TH 1
Gipsfaserplatten 2-lagig (BSK) | WUN-H2-E01-T01 | CEILING | A1 0.1 m | 1165Dfl0000085001/03 | m² | Trockenbauarbeiten | 3 | 0.1 | 0 | 1 | Bekleidung | A1 | 0 | 0 | NEW | 3.1 | Pset_CoveringCommon - FireRating: F60; AcousticRating: -; AllplanAttributes - ash_lichte Raumhöhe: 3.100000; RoomName: TH 1
Gipsfaserplatten 2-lagig (BSK) | WUN-H2-E01-T01 | CEILING | D1 0.001 m | 1165Dfl0000085001/04 | m² | Maler- und Lackierarbeiten | 4 | 0.001 | 0 | 1 | Bekleidung | D1 | 0 | 0 | NEW | 3.1 | AllplanAttributes - ash_lichte Raumhöhe: 3.100000; RoomName: TH 1
Fliesen Großformat | WUN-H2-E01-T02 | FLOORING | Fl12 0.06 m | 1165Bfl0000088433/01 | m² | Bodenbelagsarbeiten | 1 | 0.06 | 0 | 1 | Bodenfläche | Fl12 | 0 | 0 | NEW | AllplanAttributes - Bezeichnung: Fliesen Großformat; Raumnr. Bauherr: 2.11_A2_02; ash B_Aufbau: B6; ash B_Rutschhemmung: R10
Fliesen Großformat | WUN-H2-E01-T02 | FLOORING | Fl12 0.1 m | 1165Bfl0000086251/01 | m² | Bodenbelagsarbeiten | 1 | 0.1 | 0 | 1 | Bodenfläche | Fl12 | 0 | 0 | NEW | AllplanAttributes - Bezeichnung: Fliesen Großformat; Raumnr. Bauherr: 2.11_A2_02; ash B_Aufbau: B7; ash B_Rutschhemmung: R10
Sichtbetonklasse SB3 | WUN-H2-E01-T02 | CLADDING | 03 0.001 m | 1165Sfl0000097231/01 | m² | Putz- und Stuckarbeiten | 1 | 0.001 | 0 | 1 | Seitenfläche | 03 | 0 | 0 | NEW | AllplanAttributes - Bezeichnung: Sichtbetonklasse SB3
Sichtbetonklasse SB3 | WUN-H2-E01-T02 | CLADDING | 47 0.001 m | 1165Sfl0000097231/02 | m² | Maler- und Lackierarbeiten | 2 | 0.001 | 0 | 1 | Seitenfläche | 47 | 0 | 0 | NEW
Gipsfaserplatten 2-lagig (BSK) | WUN-H2-E01-T02 | CEILING | layer 0.036 m | 1165Dfl0000027331/01 | m² | Trockenbauarbeiten | 1 | 0.036 | 0 | 1 | Deckenfläche |  | 0 | 0 | NEW | 3.1 | AllplanAttributes - Bezeichnung: Gipsfaserplatten 2-lagig (BSK); RoomName: TH 2
Gipsfaserplatten 2-lagig (BSK) | WUN-H2-E01-T02 | CEILING | Installationshöhe 0.164 m | 1165Dfl0000027331/02 | m² | Trockenbauarbeiten | 2 | 0.164 | 0 | 1 | Bekleidung | Installationshöhe | 0 | 0 | NEW | 3.1 | AllplanAttributes - ash_lichte Raumhöhe: 3.100000; RoomName: TH 2
Gipsfaserplatten 2-lagig (BSK) | WUN-H2-E01-T02 | CEILING | A1 0.1 m | 1165Dfl0000027331/03 | m² | Trockenbauarbeiten | 3 | 0.1 | 0 | 1 | Bekleidung | A1 | 0 | 0 | NEW | 3.1 | Pset_CoveringCommon - FireRating: F60; AcousticRating: -; AllplanAttributes - ash_lichte Raumhöhe: 3.100000; RoomName: TH 2
Gipsfaserplatten 2-lagig (BSK) | WUN-H2-E01-T02 | CEILING | D1 0.001 m | 1165Dfl0000027331/04 | m² | Maler- und Lackierarbeiten | 4 | 0.001 | 0 | 1 | Bekleidung | D1 | 0 | 0 | NEW | 3.1 | AllplanAttributes - ash_lichte Raumhöhe: 3.100000; RoomName: TH 2
Gipsfaserplatten 2-lagig (BSK) | WUN-H2-E01-F02 | CEILING | layer 0.036 m | 1165Dfl0000007587/01 | m² | Trockenbauarbeiten | 1 | 0.036 | 0 | 1 | Deckenfläche |  | 0 | 0 | NEW | 2.65 | AllplanAttributes - Bezeichnung: Gipsfaserplatten 2-lagig (BSK); RoomName: Flur
Gipsfaserplatten 2-lagig (BSK) | WUN-H2-E01-F02 | CEILING | Installationshöhe 0.614 m | 1165Dfl0000007587/02 | m² | Trockenbauarbeiten | 2 | 0.614 | 0 | 1 | Bekleidung | Installationshöhe | 0 | 0 | NEW | 2.65 | AllplanAttributes - ash_lichte Raumhöhe: 2.650000; OKFF: 0; RoomName: Flur
Gipskarton, imprägniert | WUN-H2-E01-F02 | CEILING | A1 0.1 m | 1165Dfl0000007587/03 | m² | Trockenbauarbeiten | 3 | 0.1 | 0 | 1 | Bekleidung | A1 | 0 | 0 | NEW | 2.65 | AllplanAttributes - Bezeichnung: Gipskarton, imprägniert; ash_lichte Raumhöhe: 2.650000; OKFF: 0; RoomName: Flur; Pset_CoveringCommon - FireRating: F60; AcousticRating: -
Gipsfaserplatten 2-lagig (BSK) | WUN-H2-E01-F02 | CEILING | D1 0.001 m | 1165Dfl0000007587/04 | m² | Maler- und Lackierarbeiten | 4 | 0.001 | 0 | 1 | Bekleidung | D1 | 0 | 0 | NEW | 2.65 | AllplanAttributes - ash_lichte Raumhöhe: 2.650000; OKFF: 0; RoomName: Flur
PVC Bahnenware Uni | WUN-H2-E01-F02 | FLOORING | Ku2 0.15 m | 1165Bfl0000004657/01 | m² | Bodenbelagsarbeiten | 1 | 0.15 | 0 | 1 | Bodenfläche | Ku2 | 0 | 0 | NEW | AllplanAttributes - Bezeichnung: PVC Bahnenware Uni; Raumnr. Bauherr: 2.11_A2_02; ash B_Aufbau: B9; ash B_Rutschhemmung: R9
Gipsfaserplatten 2-lagig (BSK) | WUN-H2-E01-F02 | CEILING | layer 0.036 m | 1165Dfl0000004658/01 | m² | Trockenbauarbeiten | 1 | 0.036 | 0 | 1 | Deckenfläche |  | 0 | 0 | NEW | 3.1 | AllplanAttributes - Bezeichnung: Gipsfaserplatten 2-lagig (BSK); RoomName: Sprechzimmer
Gipsfaserplatten 2-lagig (BSK) | WUN-H2-E01-F02 | CEILING | Installationshöhe 0.164 m | 1165Dfl0000004658/02 | m² | Trockenbauarbeiten | 2 | 0.164 | 0 | 1 | Bekleidung | Installationshöhe | 0 | 0 | NEW | 3.1 | AllplanAttributes - ash_lichte Raumhöhe: 3.100000; RoomName: Sprechzimmer; Pset_CoveringCommon - AcousticRating: -
Gipsfaserplatten 2-lagig (BSK) | WUN-H2-E01-F02 | CEILING | A1 0.1 m | 1165Dfl0000004658/03 | m² | Trockenbauarbeiten | 3 | 0.1 | 0 | 1 | Bekleidung | A1 | 0 | 0 | NEW | 3.1 | Pset_CoveringCommon - FireRating: F60; AcousticRating: -; AllplanAttributes - ash_lichte Raumhöhe: 3.100000; RoomName: Sprechzimmer
Gipsfaserplatten 2-lagig (BSK) | WUN-H2-E01-F02 | CEILING | D1 0.001 m | 1165Dfl0000004658/04 | m² | Maler- und Lackierarbeiten | 4 | 0.001 | 0 | 1 | Bekleidung | D1 | 0 | 0 | NEW | 3.1 | AllplanAttributes - ash_lichte Raumhöhe: 3.100000; RoomName: Sprechzimmer
 | WUN-H2-E01-F02 | CLADDING | 50 0.001 m | 1165Sfl0000129937/01 | m² | Maler- und Lackierarbeiten | 1 | 0.001 | 0 | 1 | Seitenfläche | 50 | 150 | 2500 | NEW
Handlauf | WUN-H2-E01-073 | CLADDING | 97 0.001 m | 1165Sfl0000060255/02 | m² | Maler- und Lackierarbeiten | 2 | 0.001 | 0 | 1 | Seitenfläche | 97 | 0 | 0 | NEW | AllplanAttributes - Bezeichnung: Handlauf
Handlauf | WUN-H2-E01-073 | CLADDING | 97 0.001 m | 1165Sfl0000059964/02 | m² | Maler- und Lackierarbeiten | 2 | 0.001 | 0 | 1 | Seitenfläche | 97 | 0 | 0 | NEW | AllplanAttributes - Bezeichnung: Handlauf
Handlauf | WUN-H2-E01-073 | CLADDING | 97 0.001 m | 1165Sfl0000060546/02 | m² | Maler- und Lackierarbeiten | 2 | 0.001 | 0 | 1 | Seitenfläche | 97 | 0 | 0 | NEW | AllplanAttributes - Bezeichnung: Handlauf
Gipsfaserplatten 2-lagig (BSK) | WUN-H2-E01-073 | CEILING | layer 0.036 m | 1165Dfl0000007296/01 | m² | Trockenbauarbeiten | 1 | 0.036 | 0 | 1 | Deckenfläche |  | 0 | 0 | NEW | 2.5 | AllplanAttributes - Bezeichnung: Gipsfaserplatten 2-lagig (BSK); RoomName: Flur
Gipsfaserplatten 2-lagig (BSK) | WUN-H2-E01-073 | CEILING | Installationshöhe 0.714 m | 1165Dfl0000007296/02 | m² | Trockenbauarbeiten | 2 | 0.714 | 0 | 1 | Bekleidung | Installationshöhe | 0 | 0 | NEW | 2.5 | AllplanAttributes - ash_lichte Raumhöhe: 2.500000; RoomName: Flur
Gipsfaserplatten 2-lagig (BSK) | WUN-H2-E01-073 | CEILING | A1 0.15 m | 1165Dfl0000007296/03 | m² | Trockenbauarbeiten | 3 | 0.15 | 0 | 1 | Bekleidung | A1 | 0 | 0 | NEW | 2.5 | AllplanAttributes - ash_lichte Raumhöhe: 2.500000; RoomName: Flur; Pset_CoveringCommon - AcousticRating: -
Gipsfaserplatten 2-lagig (BSK) | WUN-H2-E01-073 | CEILING | D1 0.001 m | 1165Dfl0000007296/04 | m² | Maler- und Lackierarbeiten | 4 | 0.001 | 0 | 1 | Bekleidung | D1 | 0 | 0 | NEW | 2.5 | AllplanAttributes - ash_lichte Raumhöhe: 2.500000; RoomName: Flur
Gipsfaserplatten 2-lagig (BSK) | WUN-H2-E01-073 | CEILING | layer 0.036 m | 1165Dfl0000070609/01 | m² | Trockenbauarbeiten | 1 | 0.036 | 0 | 1 | Deckenfläche |  | 0 | 0 | NEW | 2.5 | AllplanAttributes - Bezeichnung: Gipsfaserplatten 2-lagig (BSK); RoomName: Flur
Gipsfaserplatten 2-lagig (BSK) | WUN-H2-E01-073 | CEILING | Installationshöhe 0.714 m | 1165Dfl0000070609/02 | m² | Trockenbauarbeiten | 2 | 0.714 | 0 | 1 | Bekleidung | Installationshöhe | 0 | 0 | NEW | 2.5 | AllplanAttributes - ash_lichte Raumhöhe: 2.500000; RoomName: Flur
Gipsfaserplatten 2-lagig (BSK) | WUN-H2-E01-073 | CEILING | Aa 0.15 m | 1165Dfl0000070609/03 | m² | Trockenbauarbeiten | 3 | 0.15 | 0 | 1 | Bekleidung | Aa | 0 | 0 | NEW | 2.5 | AllplanAttributes - ash_lichte Raumhöhe: 2.500000; RoomName: Flur; Pset_CoveringCommon - AcousticRating: -
Gipsfaserplatten 2-lagig (BSK) | WUN-H2-E01-073 | CEILING | D1 0.001 m | 1165Dfl0000070609/04 | m² | Maler- und Lackierarbeiten | 4 | 0.001 | 0 | 1 | Bekleidung | D1 | 0 | 0 | NEW | 2.5 | AllplanAttributes - ash_lichte Raumhöhe: 2.500000; RoomName: Flur
PVC Bahnenware Holzoptik | WUN-H2-E01-073 | FLOORING | Ku1 0.15 m | 1165Bfl0000004642/01 | m² | Bodenbelagsarbeiten | 1 | 0.15 | 0 | 1 | Bodenfläche | Ku1 | 0 | 0 | NEW | AllplanAttributes - Bezeichnung: PVC Bahnenware Holzoptik; Raumnr. Bauherr: 2.11_A2_02; ash B_Aufbau: B9; ash B_Rutschhemmung: R9
Gipsfaserplatten 2-lagig (BSK) | WUN-H2-E01-073 | CEILING | layer 0.036 m | 1165Dfl0000004643/01 | m² | Trockenbauarbeiten | 1 | 0.036 | 0 | 1 | Deckenfläche |  | 0 | 0 | NEW | 3.1 | AllplanAttributes - Bezeichnung: Gipsfaserplatten 2-lagig (BSK); RoomName: Sprechzimmer
Gipsfaserplatten 2-lagig (BSK) | WUN-H2-E01-073 | CEILING | Installationshöhe 0.164 m | 1165Dfl0000004643/02 | m² | Trockenbauarbeiten | 2 | 0.164 | 0 | 1 | Bekleidung | Installationshöhe | 0 | 0 | NEW | 3.1 | AllplanAttributes - ash_lichte Raumhöhe: 3.100000; RoomName: Sprechzimmer; Pset_CoveringCommon - AcousticRating: -
Gipsfaserplatten 2-lagig (BSK) | WUN-H2-E01-073 | CEILING | A1 0.1 m | 1165Dfl0000004643/03 | m² | Trockenbauarbeiten | 3 | 0.1 | 0 | 1 | Bekleidung | A1 | 0 | 0 | NEW | 3.1 | AllplanAttributes - ash_lichte Raumhöhe: 3.100000; RoomName: Sprechzimmer; Pset_CoveringCommon - AcousticRating: -
Gipsfaserplatten 2-lagig (BSK) | WUN-H2-E01-073 | CEILING | D1 0.001 m | 1165Dfl0000004643/04 | m² | Maler- und Lackierarbeiten | 4 | 0.001 | 0 | 1 | Bekleidung | D1 | 0 | 0 | NEW | 3.1 | AllplanAttributes - ash_lichte Raumhöhe: 3.100000; RoomName: Sprechzimmer
 | WUN-H2-E01-073 | CLADDING | 49 0.001 m | 1165Sfl0000129936/01 | m² | Maler- und Lackierarbeiten | 1 | 0.001 | 0 | 1 | Seitenfläche | 49 | 150 | 3150 | NEW
Handlauf | WUN-H2-E01-073 | CLADDING | 97 0.001 m | 1165Sfl0000061419/02 | m² | Maler- und Lackierarbeiten | 2 | 0.001 | 0 | 1 | Seitenfläche | 97 | 0 | 0 | NEW | AllplanAttributes - Bezeichnung: Handlauf
Handlauf | WUN-H2-E01-073 | CLADDING | 97 0.001 m | 1165Sfl0000061710/02 | m² | Maler- und Lackierarbeiten | 2 | 0.001 | 0 | 1 | Seitenfläche | 97 | 0 | 0 | NEW | AllplanAttributes - Bezeichnung: Handlauf
Handlauf | WUN-H2-E01-073 | CLADDING | 97 0.001 m | 1165Sfl0000061128/02 | m² | Maler- und Lackierarbeiten | 2 | 0.001 | 0 | 1 | Seitenfläche | 97 | 0 | 0 | NEW | AllplanAttributes - Bezeichnung: Handlauf
Gipsfaserplatten 2-lagig (BSK) | WUN-H2-E01-073 | CEILING | layer 0.036 m | 1165Dfl0000068857/01 | m² | Trockenbauarbeiten | 1 | 0.036 | 0 | 1 | Deckenfläche |  | 0 | 0 | NEW | 2.5 | AllplanAttributes - Bezeichnung: Gipsfaserplatten 2-lagig (BSK); RoomName: Flur
Gipsfaserplatten 2-lagig (BSK) | WUN-H2-E01-073 | CEILING | Installationshöhe 0.714 m | 1165Dfl0000068857/02 | m² | Trockenbauarbeiten | 2 | 0.714 | 0 | 1 | Bekleidung | Installationshöhe | 0 | 0 | NEW | 2.5 | AllplanAttributes - ash_lichte Raumhöhe: 2.500000; RoomName: Flur
Gipsfaserplatten 2-lagig (BSK) | WUN-H2-E01-073 | CEILING | Aa 0.15 m | 1165Dfl0000068857/03 | m² | Trockenbauarbeiten | 3 | 0.15 | 0 | 1 | Bekleidung | Aa | 0 | 0 | NEW | 2.5 | AllplanAttributes - ash_lichte Raumhöhe: 2.500000; RoomName: Flur; Pset_CoveringCommon - AcousticRating: -
Gipsfaserplatten 2-lagig (BSK) | WUN-H2-E01-073 | CEILING | D1 0.001 m | 1165Dfl0000068857/04 | m² | Maler- und Lackierarbeiten | 4 | 0.001 | 0 | 1 | Bekleidung | D1 | 0 | 0 | NEW | 2.5 | AllplanAttributes - ash_lichte Raumhöhe: 2.500000; RoomName: Flur
Gipsfaserplatten 2-lagig (BSK) | WUN-H2-E01-073 | CEILING | layer 0.036 m | 1165Dfl0000007005/01 | m² | Trockenbauarbeiten | 1 | 0.036 | 0 | 1 | Deckenfläche |  | 0 | 0 | NEW | 2.5 | AllplanAttributes - Bezeichnung: Gipsfaserplatten 2-lagig (BSK); RoomName: Flur
Gipsfaserplatten 2-lagig (BSK) | WUN-H2-E01-073 | CEILING | Installationshöhe 0.714 m | 1165Dfl0000007005/02 | m² | Trockenbauarbeiten | 2 | 0.714 | 0 | 1 | Bekleidung | Installationshöhe | 0 | 0 | NEW | 2.5 | AllplanAttributes - ash_lichte Raumhöhe: 2.500000; RoomName: Flur
Gipsfaserplatten 2-lagig (BSK) | WUN-H2-E01-073 | CEILING | A1 0.15 m | 1165Dfl0000007005/03 | m² | Trockenbauarbeiten | 3 | 0.15 | 0 | 1 | Bekleidung | A1 | 0 | 0 | NEW | 2.5 | AllplanAttributes - ash_lichte Raumhöhe: 2.500000; RoomName: Flur; Pset_CoveringCommon - AcousticRating: -
Gipsfaserplatten 2-lagig (BSK) | WUN-H2-E01-073 | CEILING | D1 0.001 m | 1165Dfl0000007005/04 | m² | Maler- und Lackierarbeiten | 4 | 0.001 | 0 | 1 | Bekleidung | D1 | 0 | 0 | NEW | 2.5 | AllplanAttributes - ash_lichte Raumhöhe: 2.500000; RoomName: Flur
PVC Bahnenware Holzoptik | WUN-H2-E01-073 | FLOORING | Ku1 0.15 m | 1165Bfl0000004679/01 | m² | Bodenbelagsarbeiten | 1 | 0.15 | 0 | 1 | Bodenfläche | Ku1 | 0 | 0 | NEW | AllplanAttributes - Bezeichnung: PVC Bahnenware Holzoptik; Raumnr. Bauherr: 2.11_A2_02; ash B_Aufbau: B9; ash B_Rutschhemmung: R9
 | WUN-H2-E01-073 | CLADDING | 49 0.001 m | 1165Sfl0000129935/01 | m² | Maler- und Lackierarbeiten | 1 | 0.001 | 0 | 1 | Seitenfläche | 49 | 150 | 3150 | NEW
Handlauf | WUN-H2-E01-073 | CLADDING | 97 0.001 m | 1165Sfl0000060837/02 | m² | Maler- und Lackierarbeiten | 2 | 0.001 | 0 | 1 | Seitenfläche | 97 | 0 | 0 | NEW | AllplanAttributes - Bezeichnung: Handlauf
Gipsfaserplatten 2-lagig (BSK) | WUN-H2-E01-073 | CEILING | layer 0.036 m | 1165Dfl0000070024/01 | m² | Trockenbauarbeiten | 1 | 0.036 | 0 | 1 | Deckenfläche |  | 0 | 0 | NEW | 2.5 | AllplanAttributes - Bezeichnung: Gipsfaserplatten 2-lagig (BSK); RoomName: Flur
Gipsfaserplatten 2-lagig (BSK) | WUN-H2-E01-073 | CEILING | Installationshöhe 0.664 m | 1165Dfl0000070024/02 | m² | Trockenbauarbeiten | 2 | 0.664 | 0 | 1 | Bekleidung | Installationshöhe | 0 | 0 | NEW | 2.5 | AllplanAttributes - ash_lichte Raumhöhe: 2.500000; RoomName: Flur
Gipsfaserplatten 2-lagig (BSK) | WUN-H2-E01-073 | CEILING | Aa 0.2 m | 1165Dfl0000070024/03 | m² | Trockenbauarbeiten | 3 | 0.2 | 0 | 1 | Bekleidung | Aa | 0 | 0 | NEW | 2.5 | Pset_CoveringCommon - FireRating: F30; AcousticRating: -; AllplanAttributes - ash_lichte Raumhöhe: 2.500000; RoomName: Flur
Gipsfaserplatten 2-lagig (BSK) | WUN-H2-E01-073 | CEILING | D1 0.001 m | 1165Dfl0000070024/04 | m² | Maler- und Lackierarbeiten | 4 | 0.001 | 0 | 1 | Bekleidung | D1 | 0 | 0 | NEW | 2.5 | AllplanAttributes - ash_lichte Raumhöhe: 2.500000; RoomName: Flur
PVC Bahnenware Holzoptik | WUN-H2-E01-073 | FLOORING | Ku1 0.15 m | 1165Bfl0000004668/01 | m² | Bodenbelagsarbeiten | 1 | 0.15 | 0 | 1 | Bodenfläche | Ku1 | 0 | 0 | NEW | AllplanAttributes - Bezeichnung: PVC Bahnenware Holzoptik; Raumnr. Bauherr: 2.11_A2_02; ash B_Aufbau: B9; ash B_Rutschhemmung: R9
Gipsfaserplatten 2-lagig (BSK) | WUN-H2-E01-073 | CEILING | layer 0.036 m | 1165Dfl0000004669/01 | m² | Trockenbauarbeiten | 1 | 0.036 | 0 | 1 | Deckenfläche |  | 0 | 0 | NEW | 2.5 | AllplanAttributes - Bezeichnung: Gipsfaserplatten 2-lagig (BSK); RoomName: Flur
Gipsfaserplatten 2-lagig (BSK) | WUN-H2-E01-073 | CEILING | Installationshöhe 0.664 m | 1165Dfl0000004669/02 | m² | Trockenbauarbeiten | 2 | 0.664 | 0 | 1 | Bekleidung | Installationshöhe | 0 | 0 | NEW | 2.5 | AllplanAttributes - ash_lichte Raumhöhe: 2.500000; RoomName: Flur
Gipsfaserplatten 2-lagig (BSK) | WUN-H2-E01-073 | CEILING | A1 0.2 m | 1165Dfl0000004669/03 | m² | Trockenbauarbeiten | 3 | 0.2 | 0 | 1 | Bekleidung | A1 | 0 | 0 | NEW | 2.5 | Pset_CoveringCommon - FireRating: F30; AcousticRating: -; AllplanAttributes - ash_lichte Raumhöhe: 2.500000; RoomName: Flur
Gipsfaserplatten 2-lagig (BSK) | WUN-H2-E01-073 | CEILING | D1 0.001 m | 1165Dfl0000004669/04 | m² | Maler- und Lackierarbeiten | 4 | 0.001 | 0 | 1 | Bekleidung | D1 | 0 | 0 | NEW | 2.5 | AllplanAttributes - ash_lichte Raumhöhe: 2.500000; RoomName: Flur
 | WUN-H2-E01-073 | CLADDING | 49 0.001 m | 1165Sfl0000129934/01 | m² | Maler- und Lackierarbeiten | 1 | 0.001 | 0 | 1 | Seitenfläche | 49 | 150 | 3150 | NEW
Handlauf | WUN-H2-E01-073 | CLADDING | 97 0.001 m | 1165Sfl0000057925/02 | m² | Maler- und Lackierarbeiten | 2 | 0.001 | 0 | 1 | Seitenfläche | 97 | 0 | 0 | NEW | AllplanAttributes - Bezeichnung: Handlauf
Handlauf | WUN-H2-E01-073 | CLADDING | 97 0.001 m | 1165Sfl0000058216/02 | m² | Maler- und Lackierarbeiten | 2 | 0.001 | 0 | 1 | Seitenfläche | 97 | 0 | 0 | NEW | AllplanAttributes - Bezeichnung: Handlauf
Handlauf | WUN-H2-E01-073 | CLADDING | 97 0.001 m | 1165Sfl0000094805/02 | m² | Maler- und Lackierarbeiten | 2 | 0.001 | 0 | 1 | Seitenfläche | 97 | 0 | 0 | NEW | AllplanAttributes - Bezeichnung: Handlauf
Handlauf | WUN-H2-E01-073 | CLADDING | 97 0.001 m | 1165Sfl0000058507/02 | m² | Maler- und Lackierarbeiten | 2 | 0.001 | 0 | 1 | Seitenfläche | 97 | 0 | 0 | NEW | AllplanAttributes - Bezeichnung: Handlauf
Gipsfaserplatten 2-lagig (BSK) | WUN-H2-E01-073 | CEILING | layer 0.036 m | 1165Dfl0000006714/01 | m² | Trockenbauarbeiten | 1 | 0.036 | 0 | 1 | Deckenfläche |  | 0 | 0 | NEW | 2.5 | AllplanAttributes - Bezeichnung: Gipsfaserplatten 2-lagig (BSK); RoomName: Flur
Gipsfaserplatten 2-lagig (BSK) | WUN-H2-E01-073 | CEILING | Installationshöhe 0.714 m | 1165Dfl0000006714/02 | m² | Trockenbauarbeiten | 2 | 0.714 | 0 | 1 | Bekleidung | Installationshöhe | 0 | 0 | NEW | 2.5 | AllplanAttributes - ash_lichte Raumhöhe: 2.500000; RoomName: Flur
Gipsfaserplatten 2-lagig (BSK) | WUN-H2-E01-073 | CEILING | A1 0.15 m | 1165Dfl0000006714/03 | m² | Trockenbauarbeiten | 3 | 0.15 | 0 | 1 | Bekleidung | A1 | 0 | 0 | NEW | 2.5 | AllplanAttributes - ash_lichte Raumhöhe: 2.500000; RoomName: Flur; Pset_CoveringCommon - AcousticRating: -
Gipsfaserplatten 2-lagig (BSK) | WUN-H2-E01-073 | CEILING | D1 0.001 m | 1165Dfl0000006714/04 | m² | Maler- und Lackierarbeiten | 4 | 0.001 | 0 | 1 | Bekleidung | D1 | 0 | 0 | NEW | 2.5 | AllplanAttributes - ash_lichte Raumhöhe: 2.500000; RoomName: Flur
Gipsfaserplatten 2-lagig (BSK) | WUN-H2-E01-073 | CEILING | layer 0.036 m | 1165Dfl0000075311/01 | m² | Trockenbauarbeiten | 1 | 0.036 | 0 | 1 | Deckenfläche |  | 0 | 0 | NEW | 2.5 | AllplanAttributes - Bezeichnung: Gipsfaserplatten 2-lagig (BSK); RoomName: Flur
Gipsfaserplatten 2-lagig (BSK) | WUN-H2-E01-073 | CEILING | Installationshöhe 0.714 m | 1165Dfl0000075311/02 | m² | Trockenbauarbeiten | 2 | 0.714 | 0 | 1 | Bekleidung | Installationshöhe | 0 | 0 | NEW | 2.5 | AllplanAttributes - ash_lichte Raumhöhe: 2.500000; RoomName: Flur
Gipsfaserplatten 2-lagig (BSK) | WUN-H2-E01-073 | CEILING | Aa 0.15 m | 1165Dfl0000075311/03 | m² | Trockenbauarbeiten | 3 | 0.15 | 0 | 1 | Bekleidung | Aa | 0 | 0 | NEW | 2.5 | AllplanAttributes - ash_lichte Raumhöhe: 2.500000; RoomName: Flur; Pset_CoveringCommon - AcousticRating: -
Gipsfaserplatten 2-lagig (BSK) | WUN-H2-E01-073 | CEILING | D1 0.001 m | 1165Dfl0000075311/04 | m² | Maler- und Lackierarbeiten | 4 | 0.001 | 0 | 1 | Bekleidung | D1 | 0 | 0 | NEW | 2.5 | AllplanAttributes - ash_lichte Raumhöhe: 2.500000; RoomName: Flur
PVC Bahnenware Holzoptik | WUN-H2-E01-073 | FLOORING | Ku1 0.15 m | 1165Bfl0000004703/01 | m² | Bodenbelagsarbeiten | 1 | 0.15 | 0 | 1 | Bodenfläche | Ku1 | 0 | 0 | NEW | AllplanAttributes - Bezeichnung: PVC Bahnenware Holzoptik; Raumnr. Bauherr: 2.11_A2_02; ash B_Aufbau: B9; ash B_Rutschhemmung: R9
Gipsfaserplatten 2-lagig (BSK) | WUN-H2-E01-073 | CEILING | layer 0.036 m | 1165Dfl0000004704/01 | m² | Trockenbauarbeiten | 1 | 0.036 | 0 | 1 | Deckenfläche |  | 0 | 0 | NEW | 3.1 | AllplanAttributes - Bezeichnung: Gipsfaserplatten 2-lagig (BSK); RoomName: Sprechzimmer
Gipsfaserplatten 2-lagig (BSK) | WUN-H2-E01-073 | CEILING | Installationshöhe 0.164 m | 1165Dfl0000004704/02 | m² | Trockenbauarbeiten | 2 | 0.164 | 0 | 1 | Bekleidung | Installationshöhe | 0 | 0 | NEW | 3.1 | AllplanAttributes - ash_lichte Raumhöhe: 3.100000; RoomName: Sprechzimmer; Pset_CoveringCommon - AcousticRating: -
Gipsfaserplatten 2-lagig (BSK) | WUN-H2-E01-073 | CEILING | A1 0.1 m | 1165Dfl0000004704/03 | m² | Trockenbauarbeiten | 3 | 0.1 | 0 | 1 | Bekleidung | A1 | 0 | 0 | NEW | 3.1 | Pset_CoveringCommon - FireRating: -; AcousticRating: -; AllplanAttributes - ash_lichte Raumhöhe: 3.100000; RoomName: Sprechzimmer
Gipsfaserplatten 2-lagig (BSK) | WUN-H2-E01-073 | CEILING | D1 0.001 m | 1165Dfl0000004704/04 | m² | Maler- und Lackierarbeiten | 4 | 0.001 | 0 | 1 | Bekleidung | D1 | 0 | 0 | NEW | 3.1 | AllplanAttributes - ash_lichte Raumhöhe: 3.100000; RoomName: Sprechzimmer
 | WUN-H2-E01-073 | CLADDING | 49 0.001 m | 1165Sfl0000129941/01 | m² | Maler- und Lackierarbeiten | 1 | 0.001 | 0 | 1 | Seitenfläche | 49 | 150 | 3150 | NEW
Handlauf | WUN-H2-E01-073 | CLADDING | 97 0.001 m | 1165Sfl0000059671/02 | m² | Maler- und Lackierarbeiten | 2 | 0.001 | 0 | 1 | Seitenfläche | 97 | 0 | 0 | NEW | AllplanAttributes - Bezeichnung: Handlauf
Handlauf | WUN-H2-E01-073 | CLADDING | 97 0.001 m | 1165Sfl0000059380/02 | m² | Maler- und Lackierarbeiten | 2 | 0.001 | 0 | 1 | Seitenfläche | 97 | 0 | 0 | NEW | AllplanAttributes - Bezeichnung: Handlauf
Handlauf | WUN-H2-E01-073 | CLADDING | 97 0.001 m | 1165Sfl0000059089/02 | m² | Maler- und Lackierarbeiten | 2 | 0.001 | 0 | 1 | Seitenfläche | 97 | 0 | 0 | NEW | AllplanAttributes - Bezeichnung: Handlauf
Gipsfaserplatten 2-lagig (BSK) | WUN-H2-E01-073 | CEILING | layer 0.036 m | 1165Dfl0000006423/01 | m² | Trockenbauarbeiten | 1 | 0.036 | 0 | 1 | Deckenfläche |  | 0 | 0 | NEW | 2.5 | AllplanAttributes - Bezeichnung: Gipsfaserplatten 2-lagig (BSK); RoomName: Flur
Gipsfaserplatten 2-lagig (BSK) | WUN-H2-E01-073 | CEILING | Installationshöhe 0.714 m | 1165Dfl0000006423/02 | m² | Trockenbauarbeiten | 2 | 0.714 | 0 | 1 | Bekleidung | Installationshöhe | 0 | 0 | NEW | 2.5 | AllplanAttributes - ash_lichte Raumhöhe: 2.500000; RoomName: Flur
Gipsfaserplatten 2-lagig (BSK) | WUN-H2-E01-073 | CEILING | A1 0.15 m | 1165Dfl0000006423/03 | m² | Trockenbauarbeiten | 3 | 0.15 | 0 | 1 | Bekleidung | A1 | 0 | 0 | NEW | 2.5 | AllplanAttributes - ash_lichte Raumhöhe: 2.500000; RoomName: Flur; Pset_CoveringCommon - AcousticRating: -
Gipsfaserplatten 2-lagig (BSK) | WUN-H2-E01-073 | CEILING | D1 0.001 m | 1165Dfl0000006423/04 | m² | Maler- und Lackierarbeiten | 4 | 0.001 | 0 | 1 | Bekleidung | D1 | 0 | 0 | NEW | 2.5 | AllplanAttributes - ash_lichte Raumhöhe: 2.500000; RoomName: Flur
Gipsfaserplatten 2-lagig (BSK) | WUN-H2-E01-073 | CEILING | layer 0.036 m | 1165Dfl0000076476/01 | m² | Trockenbauarbeiten | 1 | 0.036 | 0 | 1 | Deckenfläche |  | 0 | 0 | NEW | 2.5 | AllplanAttributes - Bezeichnung: Gipsfaserplatten 2-lagig (BSK); RoomName: Flur
Gipsfaserplatten 2-lagig (BSK) | WUN-H2-E01-073 | CEILING | Installationshöhe 0.714 m | 1165Dfl0000076476/02 | m² | Trockenbauarbeiten | 2 | 0.714 | 0 | 1 | Bekleidung | Installationshöhe | 0 | 0 | NEW | 2.5 | AllplanAttributes - ash_lichte Raumhöhe: 2.500000; RoomName: Flur
Gipsfaserplatten 2-lagig (BSK) | WUN-H2-E01-073 | CEILING | Aa 0.15 m | 1165Dfl0000076476/03 | m² | Trockenbauarbeiten | 3 | 0.15 | 0 | 1 | Bekleidung | Aa | 0 | 0 | NEW | 2.5 | AllplanAttributes - ash_lichte Raumhöhe: 2.500000; RoomName: Flur; Pset_CoveringCommon - AcousticRating: -
Gipsfaserplatten 2-lagig (BSK) | WUN-H2-E01-073 | CEILING | D1 0.001 m | 1165Dfl0000076476/04 | m² | Maler- und Lackierarbeiten | 4 | 0.001 | 0 | 1 | Bekleidung | D1 | 0 | 0 | NEW | 2.5 | AllplanAttributes - ash_lichte Raumhöhe: 2.500000; RoomName: Flur
PVC Bahnenware Holzoptik | WUN-H2-E01-073 | FLOORING | Ku1 0.15 m | 1165Bfl0000004727/01 | m² | Bodenbelagsarbeiten | 1 | 0.15 | 0 | 1 | Bodenfläche | Ku1 | 0 | 0 | NEW | AllplanAttributes - Bezeichnung: PVC Bahnenware Holzoptik; Raumnr. Bauherr: 2.11_A2_02; ash B_Aufbau: B9; ash B_Rutschhemmung: R9
Gipsfaserplatten 2-lagig (BSK) | WUN-H2-E01-073 | CEILING | layer 0.036 m | 1165Dfl0000004728/01 | m² | Trockenbauarbeiten | 1 | 0.036 | 0 | 1 | Deckenfläche |  | 0 | 0 | NEW | 3.1 | AllplanAttributes - Bezeichnung: Gipsfaserplatten 2-lagig (BSK); RoomName: Sprechzimmer
Gipsfaserplatten 2-lagig (BSK) | WUN-H2-E01-073 | CEILING | Installationshöhe 0.164 m | 1165Dfl0000004728/02 | m² | Trockenbauarbeiten | 2 | 0.164 | 0 | 1 | Bekleidung | Installationshöhe | 0 | 0 | NEW | 3.1 | AllplanAttributes - ash_lichte Raumhöhe: 3.100000; RoomName: Sprechzimmer; Pset_CoveringCommon - AcousticRating: -
Gipsfaserplatten 2-lagig (BSK) | WUN-H2-E01-073 | CEILING | A1 0.1 m | 1165Dfl0000004728/03 | m² | Trockenbauarbeiten | 3 | 0.1 | 0 | 1 | Bekleidung | A1 | 0 | 0 | NEW | 3.1 | AllplanAttributes - ash_lichte Raumhöhe: 3.100000; RoomName: Sprechzimmer; Pset_CoveringCommon - AcousticRating: -
Gipsfaserplatten 2-lagig (BSK) | WUN-H2-E01-073 | CEILING | D1 0.001 m | 1165Dfl0000004728/04 | m² | Maler- und Lackierarbeiten | 4 | 0.001 | 0 | 1 | Bekleidung | D1 | 0 | 0 | NEW | 3.1 | AllplanAttributes - ash_lichte Raumhöhe: 3.100000; RoomName: Sprechzimmer
 | WUN-H2-E01-073 | CLADDING | 49 0.001 m | 1165Sfl0000129940/01 | m² | Maler- und Lackierarbeiten | 1 | 0.001 | 0 | 1 | Seitenfläche | 49 | 150 | 3150 | NEW
Handlauf | WUN-H2-E01-073 | CLADDING | 97 0.001 m | 1165Sfl0000062005/02 | m² | Maler- und Lackierarbeiten | 2 | 0.001 | 0 | 1 | Seitenfläche | 97 | 0 | 0 | NEW | AllplanAttributes - Bezeichnung: Handlauf
Gipsfaserplatten 2-lagig (BSK) | WUN-H2-E01-073 | CEILING | layer 0.036 m | 1165Dfl0000075891/01 | m² | Trockenbauarbeiten | 1 | 0.036 | 0 | 1 | Deckenfläche |  | 0 | 0 | NEW | 2.5 | AllplanAttributes - Bezeichnung: Gipsfaserplatten 2-lagig (BSK); RoomName: Flur
Gipsfaserplatten 2-lagig (BSK) | WUN-H2-E01-073 | CEILING | Installationshöhe 0.664 m | 1165Dfl0000075891/02 | m² | Trockenbauarbeiten | 2 | 0.664 | 0 | 1 | Bekleidung | Installationshöhe | 0 | 0 | NEW | 2.5 | AllplanAttributes - ash_lichte Raumhöhe: 2.500000; RoomName: Flur
Gipsfaserplatten 2-lagig (BSK) | WUN-H2-E01-073 | CEILING | Aa 0.2 m | 1165Dfl0000075891/03 | m² | Trockenbauarbeiten | 3 | 0.2 | 0 | 1 | Bekleidung | Aa | 0 | 0 | NEW | 2.5 | Pset_CoveringCommon - FireRating: F30; AcousticRating: -; AllplanAttributes - ash_lichte Raumhöhe: 2.500000; RoomName: Flur
Gipsfaserplatten 2-lagig (BSK) | WUN-H2-E01-073 | CEILING | D1 0.001 m | 1165Dfl0000075891/04 | m² | Maler- und Lackierarbeiten | 4 | 0.001 | 0 | 1 | Bekleidung | D1 | 0 | 0 | NEW | 2.5 | AllplanAttributes - ash_lichte Raumhöhe: 2.500000; RoomName: Flur
PVC Bahnenware Holzoptik | WUN-H2-E01-073 | FLOORING | Ku1 0.15 m | 1165Bfl0000004716/01 | m² | Bodenbelagsarbeiten | 1 | 0.15 | 0 | 1 | Bodenfläche | Ku1 | 0 | 0 | NEW | AllplanAttributes - Bezeichnung: PVC Bahnenware Holzoptik; Raumnr. Bauherr: 2.11_A2_02; ash B_Aufbau: B9; ash B_Rutschhemmung: R9
Gipsfaserplatten 2-lagig (BSK) | WUN-H2-E01-073 | CEILING | layer 0.036 m | 1165Dfl0000004717/01 | m² | Trockenbauarbeiten | 1 | 0.036 | 0 | 1 | Deckenfläche |  | 0 | 0 | NEW | 2.5 | AllplanAttributes - Bezeichnung: Gipsfaserplatten 2-lagig (BSK); RoomName: Flur
Gipsfaserplatten 2-lagig (BSK) | WUN-H2-E01-073 | CEILING | Installationshöhe 0.664 m | 1165Dfl0000004717/02 | m² | Trockenbauarbeiten | 2 | 0.664 | 0 | 1 | Bekleidung | Installationshöhe | 0 | 0 | NEW | 2.5 | AllplanAttributes - ash_lichte Raumhöhe: 2.500000; RoomName: Flur
Gipsfaserplatten 2-lagig (BSK) | WUN-H2-E01-073 | CEILING | A1 0.2 m | 1165Dfl0000004717/03 | m² | Trockenbauarbeiten | 3 | 0.2 | 0 | 1 | Bekleidung | A1 | 0 | 0 | NEW | 2.5 | Pset_CoveringCommon - FireRating: F30; AcousticRating: -; AllplanAttributes - ash_lichte Raumhöhe: 2.500000; RoomName: Flur
Gipsfaserplatten 2-lagig (BSK) | WUN-H2-E01-073 | CEILING | D1 0.001 m | 1165Dfl0000004717/04 | m² | Maler- und Lackierarbeiten | 4 | 0.001 | 0 | 1 | Bekleidung | D1 | 0 | 0 | NEW | 2.5 | AllplanAttributes - ash_lichte Raumhöhe: 2.500000; RoomName: Flur
 | WUN-H2-E01-073 | CLADDING | 49 0.001 m | 1165Sfl0000129938/01 | m² | Maler- und Lackierarbeiten | 1 | 0.001 | 0 | 1 | Seitenfläche | 49 | 150 | 3150 | NEW
PVC Holzoptik | WUN-H2-E01-F01 | FLOORING | Ku1 0.15 m | 1165Bfl0000004632/01 | m² | Bodenbelagsarbeiten | 1 | 0.15 | 0 | 1 | Bodenfläche | Ku1 | 0 | 0 | NEW | AllplanAttributes - Bezeichnung: PVC Holzoptik; ash B_Aufbau: B9; ash B_Rutschhemmung: R9
Gipsfaserplatten 2-lagig (BSK) | WUN-H2-E01-F01 | CEILING | layer 0.036 m | 1165Dfl0000004631/01 | m² | Trockenbauarbeiten | 1 | 0.036 | 0 | 1 | Deckenfläche |  | 0 | 0 | NEW | 2.75 | AllplanAttributes - Bezeichnung: Gipsfaserplatten 2-lagig (BSK); RoomName: Foyer
Gipsfaserplatten 2-lagig (BSK) | WUN-H2-E01-F01 | CEILING | Installationshöhe 0.514 m | 1165Dfl0000004631/02 | m² | Trockenbauarbeiten | 2 | 0.514 | 0 | 1 | Bekleidung | Installationshöhe | 0 | 0 | NEW | 2.75 | AllplanAttributes - ash_lichte Raumhöhe: 2.750000; RoomName: Foyer
Gipsfaserplatten 2-lagig (BSK) | WUN-H2-E01-F01 | CEILING | A1 0.1 m | 1165Dfl0000004631/03 | m² | Trockenbauarbeiten | 3 | 0.1 | 0 | 1 | Bekleidung | A1 | 0 | 0 | NEW | 2.75 | Pset_CoveringCommon - FireRating: F30; AcousticRating: -; AllplanAttributes - ash_lichte Raumhöhe: 2.750000; RoomName: Foyer
Gipsfaserplatten 2-lagig (BSK) | WUN-H2-E01-F01 | CEILING | D1 0.001 m | 1165Dfl0000004631/04 | m² | Maler- und Lackierarbeiten | 4 | 0.001 | 0 | 1 | Bekleidung | D1 | 0 | 0 | NEW | 2.75 | AllplanAttributes - ash_lichte Raumhöhe: 2.750000; RoomName: Foyer
 | WUN-H2-E01-F01 | CLADDING | 49 0.001 m | 1165Sfl0000130927/01 | m² | Maler- und Lackierarbeiten | 1 | 0.001 | 0 | 1 | Seitenfläche | 49 | 150 | 2500 | NEW
Acrovyn | WUN-H2-E01-F08 | CLADDING | 84 0.001 m | 1165Sfl0000051796/02 | m² | Maler- und Lackierarbeiten | 2 | 0.001 | 0 | 1 | Seitenfläche | 84 | 0 | 0 | NEW | AllplanAttributes - Bezeichnung: Acrovyn
Handlauf | WUN-H2-E01-F08 | CLADDING | 97 0.001 m | 1165Sfl0000094271/02 | m² | Maler- und Lackierarbeiten | 2 | 0.001 | 0 | 1 | Seitenfläche | 97 | 0 | 0 | NEW | AllplanAttributes - Bezeichnung: Handlauf
Handlauf | WUN-H2-E01-F08 | CLADDING | 97 0.001 m | 1165Sfl0000094623/02 | m² | Maler- und Lackierarbeiten | 2 | 0.001 | 0 | 1 | Seitenfläche | 97 | 0 | 0 | NEW | AllplanAttributes - Bezeichnung: Handlauf
Gipsfaserplatten 2-lagig (BSK) | WUN-H2-E01-F08 | CEILING | layer 0.036 m | 1165Dfl0000074726/01 | m² | Trockenbauarbeiten | 1 | 0.036 | 0 | 1 | Deckenfläche |  | 0 | 0 | NEW | 2.5 | AllplanAttributes - Bezeichnung: Gipsfaserplatten 2-lagig (BSK); RoomName: Flur
Gipsfaserplatten 2-lagig (BSK) | WUN-H2-E01-F08 | CEILING | Installationshöhe 0.664 m | 1165Dfl0000074726/02 | m² | Trockenbauarbeiten | 2 | 0.664 | 0 | 1 | Bekleidung | Installationshöhe | 0 | 0 | NEW | 2.5 | AllplanAttributes - ash_lichte Raumhöhe: 2.500000; RoomName: Flur
Gipsfaserplatten 2-lagig (BSK) | WUN-H2-E01-F08 | CEILING | Aa 0.2 m | 1165Dfl0000074726/03 | m² | Trockenbauarbeiten | 3 | 0.2 | 0 | 1 | Bekleidung | Aa | 0 | 0 | NEW | 2.5 | Pset_CoveringCommon - FireRating: F30; AcousticRating: -; AllplanAttributes - ash_lichte Raumhöhe: 2.500000; RoomName: Flur
Gipsfaserplatten 2-lagig (BSK) | WUN-H2-E01-F08 | CEILING | D1 0.001 m | 1165Dfl0000074726/04 | m² | Maler- und Lackierarbeiten | 4 | 0.001 | 0 | 1 | Bekleidung | D1 | 0 | 0 | NEW | 2.5 | AllplanAttributes - ash_lichte Raumhöhe: 2.500000; RoomName: Flur
PVC Bahnenware Holzoptik | WUN-H2-E01-F08 | FLOORING | Ku1 0.15 m | 1165Bfl0000004692/01 | m² | Bodenbelagsarbeiten | 1 | 0.15 | 0 | 1 | Bodenfläche | Ku1 | 0 | 0 | NEW | AllplanAttributes - Bezeichnung: PVC Bahnenware Holzoptik; Raumnr. Bauherr: 2.11_A2_02; ash B_Aufbau: B9; ash B_Rutschhemmung: R9
Gipsfaserplatten 2-lagig (BSK) | WUN-H2-E01-F08 | CEILING | layer 0.036 m | 1165Dfl0000004693/01 | m² | Trockenbauarbeiten | 1 | 0.036 | 0 | 1 | Deckenfläche |  | 0 | 0 | NEW | 2.5 | AllplanAttributes - Bezeichnung: Gipsfaserplatten 2-lagig (BSK); ash_lichte Raumhöhe: 2.500000; RoomName: Flur
Gipsfaserplatten 2-lagig (BSK) | WUN-H2-E01-F08 | CEILING | Installationshöhe 0.664 m | 1165Dfl0000004693/02 | m² | Trockenbauarbeiten | 2 | 0.664 | 0 | 1 | Bekleidung | Installationshöhe | 0 | 0 | NEW | 2.5 | AllplanAttributes - ash_lichte Raumhöhe: 2.500000; RoomName: Flur
Gipsfaserplatten 2-lagig (BSK) | WUN-H2-E01-F08 | CEILING | A1 0.2 m | 1165Dfl0000004693/03 | m² | Trockenbauarbeiten | 3 | 0.2 | 0 | 1 | Bekleidung | A1 | 0 | 0 | NEW | 2.5 | Pset_CoveringCommon - FireRating: F30; AcousticRating: -; AllplanAttributes - ash_lichte Raumhöhe: 2.500000; RoomName: Flur
Gipsfaserplatten 2-lagig (BSK) | WUN-H2-E01-F08 | CEILING | D1 0.001 m | 1165Dfl0000004693/04 | m² | Maler- und Lackierarbeiten | 4 | 0.001 | 0 | 1 | Bekleidung | D1 | 0 | 0 | NEW | 2.5 | AllplanAttributes - ash_lichte Raumhöhe: 2.500000; RoomName: Flur
 | WUN-H2-E01-F08 | CLADDING | 49 0.001 m | 1165Sfl0000129939/01 | m² | Maler- und Lackierarbeiten | 1 | 0.001 | 0 | 1 | Seitenfläche | 49 | 150 | 2500 | NEW
Acrovyn | WUN-H2-E01-F03 | CLADDING | 84 0.001 m | 1165Sfl0000051505/02 | m² | Maler- und Lackierarbeiten | 2 | 0.001 | 0 | 1 | Seitenfläche | 84 | 0 | 0 | NEW | AllplanAttributes - Bezeichnung: Acrovyn
Acrovyn | WUN-H2-E01-F03 | CLADDING | 84 0.001 m | 1165Sfl0000053258/02 | m² | Maler- und Lackierarbeiten | 2 | 0.001 | 0 | 1 | Seitenfläche | 84 | 0 | 0 | NEW | AllplanAttributes - Bezeichnung: Acrovyn
Handlauf | WUN-H2-E01-F03 | CLADDING | 97 0.001 m | 1165Sfl0000054724/02 | m² | Maler- und Lackierarbeiten | 2 | 0.001 | 0 | 1 | Seitenfläche | 97 | 0 | 0 | NEW | AllplanAttributes - Bezeichnung: Handlauf
Acrovyn | WUN-H2-E01-F03 | CLADDING | 84 0.001 m | 1165Sfl0000052087/02 | m² | Maler- und Lackierarbeiten | 2 | 0.001 | 0 | 1 | Seitenfläche | 84 | 0 | 0 | NEW | AllplanAttributes - Bezeichnung: Acrovyn
Acrovyn | WUN-H2-E01-F03 | CLADDING | 84 0.001 m | 1165Sfl0000095826/02 | m² | Maler- und Lackierarbeiten | 2 | 0.001 | 0 | 1 | Seitenfläche | 84 | 0 | 0 | NEW | AllplanAttributes - Bezeichnung: Acrovyn
Handlauf | WUN-H2-E01-F03 | CLADDING | 97 0.001 m | 1165Sfl0000094989/02 | m² | Maler- und Lackierarbeiten | 2 | 0.001 | 0 | 1 | Seitenfläche | 97 | 0 | 0 | NEW | AllplanAttributes - Bezeichnung: Handlauf
PVC Bahnenware Holzoptik | WUN-H2-E01-F03 | FLOORING | Ku1 0.15 m | 1165Bfl0000004656/01 | m² | Bodenbelagsarbeiten | 1 | 0.15 | 0 | 1 | Bodenfläche | Ku1 | 0 | 0 | NEW | AllplanAttributes - Bezeichnung: PVC Bahnenware Holzoptik; Raumnr. Bauherr: 2.11_A2_02; ash B_Aufbau: B9; ash B_Rutschhemmung: R9
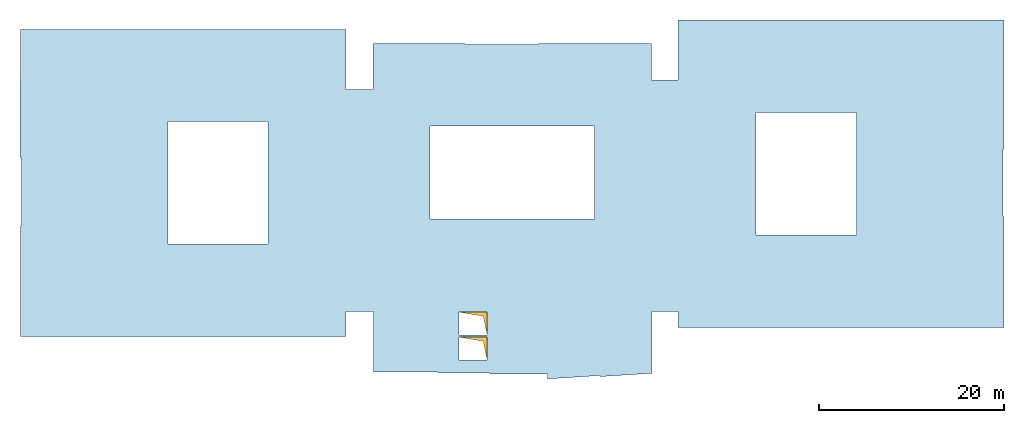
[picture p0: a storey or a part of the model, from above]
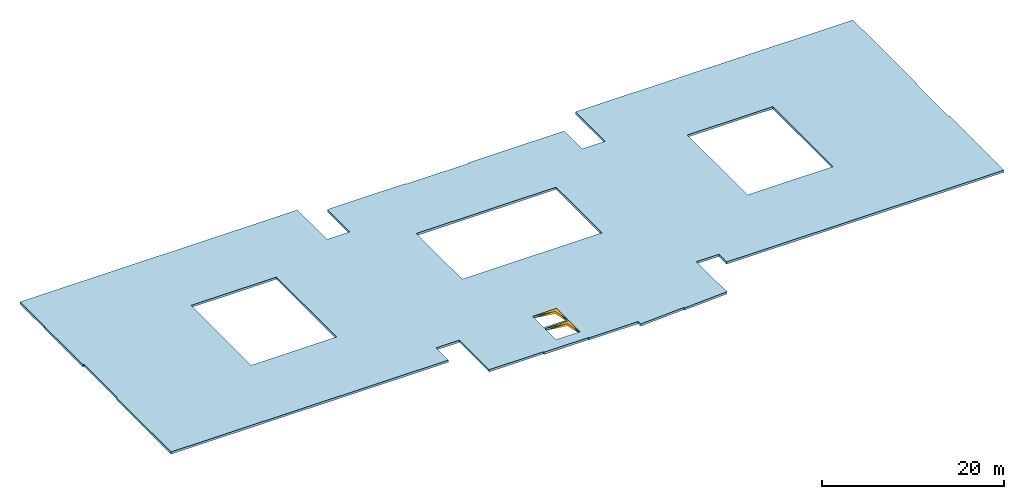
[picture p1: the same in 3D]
Properties of the parts of a building model (IFC4), part 11 of 80

# IfcCovering (3945)
Name | In | PredefinedType | Material | Allright_Bauteil_ID | Abrechnungsart | Gewerk | Schichtnummer | Schichtdicke (m) | Dicke (m) | Faktor | Objektname | AllplanAttributes, Material | Bezugshöhe | Deltahöhe | Status | D_lichte Raumhöhe [Zahl] (m)
Gipsfaserplatten 2-lagig (BSK) | WUN-H2-E01-F03 | CEILING | layer 0.036 m | 1165Dfl0000129805/01 | m² | Trockenbauarbeiten | 1 | 0.036 | 0 | 1 | Deckenfläche |  | 0 | 0 | NEW | 3.1 | AllplanAttributes - Bezeichnung: Gipsfaserplatten 2-lagig (BSK); RoomName: Flur
Gipsfaserplatten 2-lagig (BSK) | WUN-H2-E01-F03 | CEILING | Installationshöhe 0.164 m | 1165Dfl0000129805/02 | m² | Trockenbauarbeiten | 2 | 0.164 | 0 | 1 | Bekleidung | Installationshöhe | 0 | 0 | NEW | 3.1 | AllplanAttributes - ash_lichte Raumhöhe: 3.100000; RoomName: Flur; Pset_CoveringCommon - AcousticRating: -
Gipsfaserplatten 2-lagig (BSK) | WUN-H2-E01-F03 | CEILING | A1 0.1 m | 1165Dfl0000129805/03 | m² | Trockenbauarbeiten | 3 | 0.1 | 0 | 1 | Bekleidung | A1 | 0 | 0 | NEW | 3.1 | AllplanAttributes - ash_lichte Raumhöhe: 3.100000; RoomName: Flur; Pset_CoveringCommon - AcousticRating: -
Gipsfaserplatten 2-lagig (BSK) | WUN-H2-E01-F03 | CEILING | D1 0.001 m | 1165Dfl0000129805/04 | m² | Maler- und Lackierarbeiten | 4 | 0.001 | 0 | 1 | Bekleidung | D1 | 0 | 0 | NEW | 3.1 | AllplanAttributes - ash_lichte Raumhöhe: 3.100000; RoomName: Flur
Gipsfaserplatten 2-lagig (BSK) | WUN-H2-E01-F03 | CEILING | layer 0.036 m | 1165Dfl0000128738/01 | m² | Trockenbauarbeiten | 1 | 0.036 | 0 | 1 | Deckenfläche |  | 0 | 0 | NEW | 3.1 | AllplanAttributes - Bezeichnung: Gipsfaserplatten 2-lagig (BSK); RoomName: Flur
Gipsfaserplatten 2-lagig (BSK) | WUN-H2-E01-F03 | CEILING | Installationshöhe 0.164 m | 1165Dfl0000128738/02 | m² | Trockenbauarbeiten | 2 | 0.164 | 0 | 1 | Bekleidung | Installationshöhe | 0 | 0 | NEW | 3.1 | AllplanAttributes - ash_lichte Raumhöhe: 3.100000; RoomName: Flur; Pset_CoveringCommon - AcousticRating: -
Gipsfaserplatten 2-lagig (BSK) | WUN-H2-E01-F03 | CEILING | A1 0.1 m | 1165Dfl0000128738/03 | m² | Trockenbauarbeiten | 3 | 0.1 | 0 | 1 | Bekleidung | A1 | 0 | 0 | NEW | 3.1 | AllplanAttributes - ash_lichte Raumhöhe: 3.100000; RoomName: Flur; Pset_CoveringCommon - AcousticRating: -
Gipsfaserplatten 2-lagig (BSK) | WUN-H2-E01-F03 | CEILING | D1 0.001 m | 1165Dfl0000128738/04 | m² | Maler- und Lackierarbeiten | 4 | 0.001 | 0 | 1 | Bekleidung | D1 | 0 | 0 | NEW | 3.1 | AllplanAttributes - ash_lichte Raumhöhe: 3.100000; RoomName: Flur
Gipsfaserplatten 2-lagig (BSK) | WUN-H2-E01-F03 | CEILING | layer 0.036 m | 1165Dfl0000006027/01 | m² | Trockenbauarbeiten | 1 | 0.036 | 0 | 1 | Deckenfläche |  | 0 | 0 | NEW | 2.5 | AllplanAttributes - Bezeichnung: Gipsfaserplatten 2-lagig (BSK); RoomName: Flur
Gipsfaserplatten 2-lagig (BSK) | WUN-H2-E01-F03 | CEILING | Installationshöhe 0.714 m | 1165Dfl0000006027/02 | m² | Trockenbauarbeiten | 2 | 0.714 | 0 | 1 | Bekleidung | Installationshöhe | 0 | 0 | NEW | 2.5 | AllplanAttributes - ash_lichte Raumhöhe: 2.500000; RoomName: Flur
Gipsfaserplatten 2-lagig (BSK) | WUN-H2-E01-F03 | CEILING | A1 0.15 m | 1165Dfl0000006027/03 | m² | Trockenbauarbeiten | 3 | 0.15 | 0 | 1 | Bekleidung | A1 | 0 | 0 | NEW | 2.5 | AllplanAttributes - ash_lichte Raumhöhe: 2.500000; RoomName: Flur; Pset_CoveringCommon - AcousticRating: -
Gipsfaserplatten 2-lagig (BSK) | WUN-H2-E01-F03 | CEILING | D1 0.001 m | 1165Dfl0000006027/04 | m² | Maler- und Lackierarbeiten | 4 | 0.001 | 0 | 1 | Bekleidung | D1 | 0 | 0 | NEW | 2.5 | AllplanAttributes - ash_lichte Raumhöhe: 2.500000; RoomName: Flur
Gipsfaserplatten 2-lagig (BSK) | WUN-H2-E01-F03 | CEILING | layer 0.036 m | 1165Dfl0000071194/01 | m² | Trockenbauarbeiten | 1 | 0.036 | 0 | 1 | Deckenfläche |  | 0 | 0 | NEW | 2.5 | AllplanAttributes - Bezeichnung: Gipsfaserplatten 2-lagig (BSK); RoomName: Flur
Gipsfaserplatten 2-lagig (BSK) | WUN-H2-E01-F03 | CEILING | Installationshöhe 0.714 m | 1165Dfl0000071194/02 | m² | Trockenbauarbeiten | 2 | 0.714 | 0 | 1 | Bekleidung | Installationshöhe | 0 | 0 | NEW | 2.5 | AllplanAttributes - ash_lichte Raumhöhe: 2.500000; RoomName: Flur
Gipsfaserplatten 2-lagig (BSK) | WUN-H2-E01-F03 | CEILING | Aa 0.15 m | 1165Dfl0000071194/03 | m² | Trockenbauarbeiten | 3 | 0.15 | 0 | 1 | Bekleidung | Aa | 0 | 0 | NEW | 2.5 | AllplanAttributes - ash_lichte Raumhöhe: 2.500000; RoomName: Flur; Pset_CoveringCommon - AcousticRating: -
Gipsfaserplatten 2-lagig (BSK) | WUN-H2-E01-F03 | CEILING | D1 0.001 m | 1165Dfl0000071194/04 | m² | Maler- und Lackierarbeiten | 4 | 0.001 | 0 | 1 | Bekleidung | D1 | 0 | 0 | NEW | 2.5 | AllplanAttributes - ash_lichte Raumhöhe: 2.500000; RoomName: Flur
 | WUN-H2-E01-F03 | CLADDING | 49 0.001 m | 1165Sfl0000130955/01 | m² | Maler- und Lackierarbeiten | 1 | 0.001 | 0 | 1 | Seitenfläche | 49 | 150 | 2500 | NEW
Sichtbetonklasse SB3 | WUN-H2-E01-T03 | CLADDING | 03 0.001 m | 1165Sfl0000097230/02 | m² | Putz- und Stuckarbeiten | 2 | 0.001 | 0 | 1 | Seitenfläche | 03 | 0 | 0 | NEW | AllplanAttributes - Bezeichnung: Sichtbetonklasse SB3
Sichtbetonklasse SB3 | WUN-H2-E01-T03 | CLADDING | 47 0.001 m | 1165Sfl0000097230/04 | m² | Maler- und Lackierarbeiten | 4 | 0.001 | 0 | 1 | Seitenfläche | 47 | 0 | 0 | NEW
Gipsfaserplatten 2-lagig (BSK) | WUN-H2-E01-T03 | CEILING | layer 0.036 m | 1165Dfl0000027911/01 | m² | Trockenbauarbeiten | 1 | 0.036 | 0 | 1 | Deckenfläche |  | 0 | 0 | NEW | 3.1 | AllplanAttributes - Bezeichnung: Gipsfaserplatten 2-lagig (BSK); RoomName: TH 3
Gipsfaserplatten 2-lagig (BSK) | WUN-H2-E01-T03 | CEILING | Installationshöhe 0.164 m | 1165Dfl0000027911/02 | m² | Trockenbauarbeiten | 2 | 0.164 | 0 | 1 | Bekleidung | Installationshöhe | 0 | 0 | NEW | 3.1 | AllplanAttributes - ash_lichte Raumhöhe: 3.100000; RoomName: TH 3
Gipsfaserplatten 2-lagig (BSK) | WUN-H2-E01-T03 | CEILING | A1 0.1 m | 1165Dfl0000027911/03 | m² | Trockenbauarbeiten | 3 | 0.1 | 0 | 1 | Bekleidung | A1 | 0 | 0 | NEW | 3.1 | Pset_CoveringCommon - FireRating: F60; AcousticRating: -; AllplanAttributes - ash_lichte Raumhöhe: 3.100000; RoomName: TH 3
Gipsfaserplatten 2-lagig (BSK) | WUN-H2-E01-T03 | CEILING | D1 0.001 m | 1165Dfl0000027911/04 | m² | Maler- und Lackierarbeiten | 4 | 0.001 | 0 | 1 | Bekleidung | D1 | 0 | 0 | NEW | 3.1 | AllplanAttributes - ash_lichte Raumhöhe: 3.100000; RoomName: TH 3
Fliesen Großformat | WUN-H2-E01-T03 | FLOORING | Fl12 0.06 m | 1165Bfl0000088796/01 | m² | Bodenbelagsarbeiten | 1 | 0.06 | 0 | 1 | Bodenfläche | Fl12 | 0 | 0 | NEW | AllplanAttributes - Bezeichnung: Fliesen Großformat; Raumnr. Bauherr: 2.11_A2_02; ash B_Aufbau: B6; ash B_Rutschhemmung: R10
Fliesen Großformat | WUN-H2-E01-T03 | FLOORING | Fl12 0.1 m | 1165Bfl0000086603/01 | m² | Bodenbelagsarbeiten | 1 | 0.1 | 0 | 1 | Bodenfläche | Fl12 | 0 | 0 | NEW | AllplanAttributes - Bezeichnung: Fliesen Großformat; Raumnr. Bauherr: 2.11_A2_02; ash B_Aufbau: B7; ash B_Rutschhemmung: R10
Handlauf | WUN-H2-E01-F07 | CLADDING | 97 0.001 m | 1165Sfl0000056761/02 | m² | Maler- und Lackierarbeiten | 2 | 0.001 | 0 | 1 | Seitenfläche | 97 | 0 | 0 | NEW | AllplanAttributes - Bezeichnung: Handlauf
Handlauf | WUN-H2-E01-F07 | CLADDING | 97 0.001 m | 1165Sfl0000095167/02 | m² | Maler- und Lackierarbeiten | 2 | 0.001 | 0 | 1 | Seitenfläche | 97 | 0 | 0 | NEW | AllplanAttributes - Bezeichnung: Handlauf
Handlauf | WUN-H2-E01-F07 | CLADDING | 97 0.001 m | 1165Sfl0000057343/02 | m² | Maler- und Lackierarbeiten | 2 | 0.001 | 0 | 1 | Seitenfläche | 97 | 0 | 0 | NEW | AllplanAttributes - Bezeichnung: Handlauf
Handlauf | WUN-H2-E01-F07 | CLADDING | 97 0.001 m | 1165Sfl0000057052/02 | m² | Maler- und Lackierarbeiten | 2 | 0.001 | 0 | 1 | Seitenfläche | 97 | 0 | 0 | NEW | AllplanAttributes - Bezeichnung: Handlauf
PVC Bahnenware Holzoptik | WUN-H2-E01-F07 | FLOORING | Ku1 0.15 m | 1165Bfl0000004816/01 | m² | Bodenbelagsarbeiten | 1 | 0.15 | 0 | 1 | Bodenfläche | Ku1 | 0 | 0 | NEW | AllplanAttributes - Bezeichnung: PVC Bahnenware Holzoptik; Raumnr. Bauherr: 2.11_A2_02; ash B_Aufbau: B9; ash B_Rutschhemmung: R9
Gipsfaserplatten 2-lagig (BSK) | WUN-H2-E01-F07 | CEILING | layer 0.036 m | 1165Dfl0000124380/01 | m² | Trockenbauarbeiten | 1 | 0.036 | 0 | 1 | Deckenfläche |  | 0 | 0 | NEW | 3.1 | AllplanAttributes - Bezeichnung: Gipsfaserplatten 2-lagig (BSK); RoomName: Flur
Gipsfaserplatten 2-lagig (BSK) | WUN-H2-E01-F07 | CEILING | Installationshöhe 0.164 m | 1165Dfl0000124380/02 | m² | Trockenbauarbeiten | 2 | 0.164 | 0 | 1 | Bekleidung | Installationshöhe | 0 | 0 | NEW | 3.1 | AllplanAttributes - ash_lichte Raumhöhe: 3.100000; RoomName: Flur; Pset_CoveringCommon - AcousticRating: -
Gipsfaserplatten 2-lagig (BSK) | WUN-H2-E01-F07 | CEILING | A1 0.1 m | 1165Dfl0000124380/03 | m² | Trockenbauarbeiten | 3 | 0.1 | 0 | 1 | Bekleidung | A1 | 0 | 0 | NEW | 3.1 | AllplanAttributes - ash_lichte Raumhöhe: 3.100000; RoomName: Flur; Pset_CoveringCommon - AcousticRating: -
Gipsfaserplatten 2-lagig (BSK) | WUN-H2-E01-F07 | CEILING | D1 0.001 m | 1165Dfl0000124380/04 | m² | Maler- und Lackierarbeiten | 4 | 0.001 | 0 | 1 | Bekleidung | D1 | 0 | 0 | NEW | 3.1 | AllplanAttributes - ash_lichte Raumhöhe: 3.100000; RoomName: Flur
Gipsfaserplatten 2-lagig (BSK) | WUN-H2-E01-F07 | CEILING | layer 0.036 m | 1165Dfl0000073844/01 | m² | Trockenbauarbeiten | 1 | 0.036 | 0 | 1 | Deckenfläche |  | 0 | 0 | NEW | 2.5 | AllplanAttributes - Bezeichnung: Gipsfaserplatten 2-lagig (BSK); RoomName: Flur
Gipsfaserplatten 2-lagig (BSK) | WUN-H2-E01-F07 | CEILING | Installationshöhe 0.714 m | 1165Dfl0000073844/02 | m² | Trockenbauarbeiten | 2 | 0.714 | 0 | 1 | Bekleidung | Installationshöhe | 0 | 0 | NEW | 2.5 | AllplanAttributes - ash_lichte Raumhöhe: 2.500000; RoomName: Flur
Gipsfaserplatten 2-lagig (BSK) | WUN-H2-E01-F07 | CEILING | Aa 0.15 m | 1165Dfl0000073844/03 | m² | Trockenbauarbeiten | 3 | 0.15 | 0 | 1 | Bekleidung | Aa | 0 | 0 | NEW | 2.5 | AllplanAttributes - ash_lichte Raumhöhe: 2.500000; RoomName: Flur; Pset_CoveringCommon - AcousticRating: -
Gipsfaserplatten 2-lagig (BSK) | WUN-H2-E01-F07 | CEILING | D1 0.001 m | 1165Dfl0000073844/04 | m² | Maler- und Lackierarbeiten | 4 | 0.001 | 0 | 1 | Bekleidung | D1 | 0 | 0 | NEW | 2.5 | AllplanAttributes - ash_lichte Raumhöhe: 2.500000; RoomName: Flur
Gipsfaserplatten 2-lagig (BSK) | WUN-H2-E01-F07 | CEILING | layer 0.036 m | 1165Dfl0000074435/01 | m² | Trockenbauarbeiten | 1 | 0.036 | 0 | 1 | Deckenfläche |  | 0 | 0 | NEW | 2.5 | AllplanAttributes - Bezeichnung: Gipsfaserplatten 2-lagig (BSK); RoomName: Flur
Gipsfaserplatten 2-lagig (BSK) | WUN-H2-E01-F07 | CEILING | Installationshöhe 0.714 m | 1165Dfl0000074435/02 | m² | Trockenbauarbeiten | 2 | 0.714 | 0 | 1 | Bekleidung | Installationshöhe | 0 | 0 | NEW | 2.5 | AllplanAttributes - ash_lichte Raumhöhe: 2.500000; RoomName: Flur
Gipsfaserplatten 2-lagig (BSK) | WUN-H2-E01-F07 | CEILING | A1 0.15 m | 1165Dfl0000074435/03 | m² | Trockenbauarbeiten | 3 | 0.15 | 0 | 1 | Bekleidung | A1 | 0 | 0 | NEW | 2.5 | AllplanAttributes - ash_lichte Raumhöhe: 2.500000; RoomName: Flur; Pset_CoveringCommon - AcousticRating: -
Gipsfaserplatten 2-lagig (BSK) | WUN-H2-E01-F07 | CEILING | D1 0.001 m | 1165Dfl0000074435/04 | m² | Maler- und Lackierarbeiten | 4 | 0.001 | 0 | 1 | Bekleidung | D1 | 0 | 0 | NEW | 2.5 | AllplanAttributes - ash_lichte Raumhöhe: 2.500000; RoomName: Flur
Gipsfaserplatten 2-lagig (BSK) | WUN-H2-E01-F07 | CEILING | layer 0.036 m | 1165Dfl0000126361/01 | m² | Trockenbauarbeiten | 1 | 0.036 | 0 | 1 | Deckenfläche |  | 0 | 0 | NEW | 3.1 | AllplanAttributes - Bezeichnung: Gipsfaserplatten 2-lagig (BSK); RoomName: Flur
Gipsfaserplatten 2-lagig (BSK) | WUN-H2-E01-F07 | CEILING | Installationshöhe 0.164 m | 1165Dfl0000126361/02 | m² | Trockenbauarbeiten | 2 | 0.164 | 0 | 1 | Bekleidung | Installationshöhe | 0 | 0 | NEW | 3.1 | AllplanAttributes - ash_lichte Raumhöhe: 3.100000; RoomName: Flur; Pset_CoveringCommon - AcousticRating: -
Gipsfaserplatten 2-lagig (BSK) | WUN-H2-E01-F07 | CEILING | A1 0.1 m | 1165Dfl0000126361/03 | m² | Trockenbauarbeiten | 3 | 0.1 | 0 | 1 | Bekleidung | A1 | 0 | 0 | NEW | 3.1 | AllplanAttributes - ash_lichte Raumhöhe: 3.100000; RoomName: Flur; Pset_CoveringCommon - AcousticRating: -
Gipsfaserplatten 2-lagig (BSK) | WUN-H2-E01-F07 | CEILING | D1 0.001 m | 1165Dfl0000126361/04 | m² | Maler- und Lackierarbeiten | 4 | 0.001 | 0 | 1 | Bekleidung | D1 | 0 | 0 | NEW | 3.1 | AllplanAttributes - ash_lichte Raumhöhe: 3.100000; RoomName: Flur
 | WUN-H2-E01-F07 | CLADDING | 49 0.001 m | 1165Sfl0000130950/01 | m² | Maler- und Lackierarbeiten | 1 | 0.001 | 0 | 1 | Seitenfläche | 49 | 150 | 2500 | NEW
a-sh Abschluss Abhangdecke | H2 Ebene +1 | CEILING |  | 1166HWa0000663981 | m² |  |  |  |  |  | Gesamtwand |  |  |  | NEW | AllplanAttributes - Bezeichnung: a-sh Abschluss Abhangdecke; Attributset-Objekt: Covering; Object Layer Attributes #1, 2D Interaktion: yes; Object Layer Attributes #1, Gewerk: Trockenbauarbeiten; Object Layer Attributes #1, Material: A; Object Layer Attributes #1, Attributset-Objekt: Covering; Object Layer Attributes #1, Allright_Bauteil_ID: 1166Wa 0000663982; Object Layer Attributes #1, Abrechnungsart: m²; Object Layer Attributes #1, Objektname: Wand; Pset_CoveringCommon - IsExternal: no; FireRating: -; ThermalTransmittance: 0 W/K/m2; Reference: Reference
a-sh Abschluss Abhangdecke | H2 Ebene +1 | CEILING |  | 1166HWa0000663990 | m² |  |  |  |  |  | Gesamtwand |  |  |  | NEW | AllplanAttributes - Bezeichnung: a-sh Abschluss Abhangdecke; Attributset-Objekt: Covering; Object Layer Attributes #1, 2D Interaktion: yes; Object Layer Attributes #1, Gewerk: Trockenbauarbeiten; Object Layer Attributes #1, Material: A; Object Layer Attributes #1, Attributset-Objekt: Covering; Object Layer Attributes #1, Allright_Bauteil_ID: 1166Wa 0000663991; Object Layer Attributes #1, Abrechnungsart: m²; Object Layer Attributes #1, Objektname: Wand; Pset_CoveringCommon - IsExternal: no; FireRating: -; ThermalTransmittance: 0 W/K/m2; Reference: Reference
a-sh Abschluss Abhangdecke | H2 Ebene +1 | CEILING |  | 1166HWa0000663995 | m² |  |  |  |  |  | Gesamtwand |  |  |  | NEW | AllplanAttributes - Bezeichnung: a-sh Abschluss Abhangdecke; Attributset-Objekt: Covering; Object Layer Attributes #1, 2D Interaktion: yes; Object Layer Attributes #1, Gewerk: Trockenbauarbeiten; Object Layer Attributes #1, Material: A; Object Layer Attributes #1, Attributset-Objekt: Covering; Object Layer Attributes #1, Allright_Bauteil_ID: 1166Wa 0000663996; Object Layer Attributes #1, Abrechnungsart: m²; Object Layer Attributes #1, Objektname: Wand; Pset_CoveringCommon - IsExternal: no; FireRating: -; ThermalTransmittance: 0 W/K/m2; Reference: Reference
a-sh Abschluss Abhangdecke | H2 Ebene +1 | CEILING |  | 1166HWa0000664000 | m² |  |  |  |  |  | Gesamtwand |  |  |  | NEW | AllplanAttributes - Bezeichnung: a-sh Abschluss Abhangdecke; Attributset-Objekt: Covering; Object Layer Attributes #1, 2D Interaktion: yes; Object Layer Attributes #1, Gewerk: Trockenbauarbeiten; Object Layer Attributes #1, Material: A; Object Layer Attributes #1, Attributset-Objekt: Covering; Object Layer Attributes #1, Allright_Bauteil_ID: 1166Wa 0000664001; Object Layer Attributes #1, Abrechnungsart: m²; Object Layer Attributes #1, Objektname: Wand; Pset_CoveringCommon - IsExternal: no; FireRating: -; ThermalTransmittance: 0 W/K/m2; Reference: Reference
a-sh Abschluss Abhangdecke | H2 Ebene +1 | CEILING |  | 1166HWa0000664005 | m² |  |  |  |  |  | Gesamtwand |  |  |  | NEW | AllplanAttributes - Bezeichnung: a-sh Abschluss Abhangdecke; Attributset-Objekt: Covering; Object Layer Attributes #1, 2D Interaktion: yes; Object Layer Attributes #1, Gewerk: Trockenbauarbeiten; Object Layer Attributes #1, Material: A; Object Layer Attributes #1, Attributset-Objekt: Covering; Object Layer Attributes #1, Allright_Bauteil_ID: 1166Wa 0000664006; Object Layer Attributes #1, Abrechnungsart: m²; Object Layer Attributes #1, Objektname: Wand; Pset_CoveringCommon - IsExternal: no; FireRating: -; ThermalTransmittance: 0 W/K/m2; Reference: Reference
a-sh Abschluss Abhangdecke | H2 Ebene +1 | CEILING |  | 1166HWa0000664010 | m² |  |  |  |  |  | Gesamtwand |  |  |  | NEW | AllplanAttributes - Bezeichnung: a-sh Abschluss Abhangdecke; Attributset-Objekt: Covering; Object Layer Attributes #1, 2D Interaktion: yes; Object Layer Attributes #1, Gewerk: Trockenbauarbeiten; Object Layer Attributes #1, Material: A; Object Layer Attributes #1, Attributset-Objekt: Covering; Object Layer Attributes #1, Allright_Bauteil_ID: 1166Wa 0000664011; Object Layer Attributes #1, Abrechnungsart: m²; Object Layer Attributes #1, Objektname: Wand; Pset_CoveringCommon - IsExternal: no; FireRating: -; ThermalTransmittance: 0 W/K/m2; Reference: Reference
a-sh Abschluss Abhangdecke | H2 Ebene +1 | CEILING |  | 1166HWa0000664015 | m² |  |  |  |  |  | Gesamtwand |  |  |  | NEW | AllplanAttributes - Bezeichnung: a-sh Abschluss Abhangdecke; Attributset-Objekt: Covering; Object Layer Attributes #1, 2D Interaktion: yes; Object Layer Attributes #1, Gewerk: Trockenbauarbeiten; Object Layer Attributes #1, Material: A; Object Layer Attributes #1, Attributset-Objekt: Covering; Object Layer Attributes #1, Allright_Bauteil_ID: 1166Wa 0000664016; Object Layer Attributes #1, Abrechnungsart: m²; Object Layer Attributes #1, Objektname: Wand; Pset_CoveringCommon - IsExternal: no; FireRating: -; ThermalTransmittance: 0 W/K/m2; Reference: Reference
a-sh Abschluss Abhangdecke | H2 Ebene +1 | CEILING |  | 1166HWa0000664020 | m² |  |  |  |  |  | Gesamtwand |  |  |  | NEW | AllplanAttributes - Bezeichnung: a-sh Abschluss Abhangdecke; Attributset-Objekt: Covering; Object Layer Attributes #1, 2D Interaktion: yes; Object Layer Attributes #1, Gewerk: Trockenbauarbeiten; Object Layer Attributes #1, Material: A; Object Layer Attributes #1, Tragendes Bauteil: no; Object Layer Attributes #1, Attributset-Objekt: Covering; Object Layer Attributes #1, Allright_Bauteil_ID: 1166Wa 0000664021; Object Layer Attributes #1, Abrechnungsart: m²; Object Layer Attributes #1, Objektname: Wand; Pset_CoveringCommon - IsExternal: no; FireRating: -; ThermalTransmittance: 0 W/K/m2; Reference: Reference
a-sh Abschluss Abhangdecke | H2 Ebene +1 | CEILING |  | 1166HWa0000664029 | m² |  |  |  |  |  | Gesamtwand |  |  |  | NEW | AllplanAttributes - Bezeichnung: a-sh Abschluss Abhangdecke; Attributset-Objekt: Covering; Object Layer Attributes #1, 2D Interaktion: yes; Object Layer Attributes #1, Gewerk: Trockenbauarbeiten; Object Layer Attributes #1, Material: A; Object Layer Attributes #1, Tragendes Bauteil: no; Object Layer Attributes #1, Attributset-Objekt: Covering; Object Layer Attributes #1, Allright_Bauteil_ID: 1166Wa 0000664030; Object Layer Attributes #1, Abrechnungsart: m²; Object Layer Attributes #1, Objektname: Wand; Pset_CoveringCommon - IsExternal: no; FireRating: -; ThermalTransmittance: 0 W/K/m2; Reference: Reference
a-sh Abschluss Abhangdecke | H2 Ebene +1 | CEILING |  | 1166HWa0000664034 | m² |  |  |  |  |  | Gesamtwand |  |  |  | NEW | AllplanAttributes - Bezeichnung: a-sh Abschluss Abhangdecke; Attributset-Objekt: Covering; Object Layer Attributes #1, 2D Interaktion: yes; Object Layer Attributes #1, Gewerk: Trockenbauarbeiten; Object Layer Attributes #1, Material: A; Object Layer Attributes #1, Tragendes Bauteil: no; Object Layer Attributes #1, Attributset-Objekt: Covering; Object Layer Attributes #1, Allright_Bauteil_ID: 1166Wa 0000664035; Object Layer Attributes #1, Abrechnungsart: m²; Object Layer Attributes #1, Objektname: Wand; Pset_CoveringCommon - IsExternal: no; FireRating: -; ThermalTransmittance: 0 W/K/m2; Reference: Reference
a-sh Abschluss Abhangdecke | H2 Ebene +1 | CEILING |  | 1166HWa0000664039 | m² |  |  |  |  |  | Gesamtwand |  |  |  | NEW | AllplanAttributes - Bezeichnung: a-sh Abschluss Abhangdecke; Attributset-Objekt: Covering; Object Layer Attributes #1, 2D Interaktion: yes; Object Layer Attributes #1, Gewerk: Trockenbauarbeiten; Object Layer Attributes #1, Material: A; Object Layer Attributes #1, Attributset-Objekt: Covering; Object Layer Attributes #1, Allright_Bauteil_ID: 1166Wa 0000664040; Object Layer Attributes #1, Abrechnungsart: m²; Object Layer Attributes #1, Objektname: Wand; Pset_CoveringCommon - IsExternal: no; FireRating: -; ThermalTransmittance: 0 W/K/m2; Reference: Reference
a-sh Abschluss Abhangdecke | H2 Ebene +1 | CEILING |  | 1166HWa0000664044 | m² |  |  |  |  |  | Gesamtwand |  |  |  | NEW | AllplanAttributes - Bezeichnung: a-sh Abschluss Abhangdecke; Attributset-Objekt: Covering; Object Layer Attributes #1, 2D Interaktion: yes; Object Layer Attributes #1, Gewerk: Trockenbauarbeiten; Object Layer Attributes #1, Material: A; Object Layer Attributes #1, Attributset-Objekt: Covering; Object Layer Attributes #1, Allright_Bauteil_ID: 1166Wa 0000664045; Object Layer Attributes #1, Abrechnungsart: m²; Object Layer Attributes #1, Objektname: Wand; Pset_CoveringCommon - IsExternal: no; FireRating: -; ThermalTransmittance: 0 W/K/m2; Reference: Reference
a-sh Abschluss Abhangdecke | H2 Ebene +1 | CEILING |  | 1166HWa0000664049 | m² |  |  |  |  |  | Gesamtwand |  |  |  | NEW | AllplanAttributes - Bezeichnung: a-sh Abschluss Abhangdecke; Attributset-Objekt: Covering; Object Layer Attributes #1, 2D Interaktion: yes; Object Layer Attributes #1, Gewerk: Trockenbauarbeiten; Object Layer Attributes #1, Material: A; Object Layer Attributes #1, Attributset-Objekt: Covering; Object Layer Attributes #1, Allright_Bauteil_ID: 1166Wa 0000664050; Object Layer Attributes #1, Abrechnungsart: m²; Object Layer Attributes #1, Objektname: Wand; Pset_CoveringCommon - IsExternal: no; FireRating: -; ThermalTransmittance: 0 W/K/m2; Reference: Reference
a-sh Abschluss Abhangdecke | H2 Ebene +1 | CEILING |  | 1166HWa0000664054 | m² |  |  |  |  |  | Gesamtwand |  |  |  | NEW | AllplanAttributes - Bezeichnung: a-sh Abschluss Abhangdecke; Attributset-Objekt: Covering; Object Layer Attributes #1, 2D Interaktion: yes; Object Layer Attributes #1, Gewerk: Trockenbauarbeiten; Object Layer Attributes #1, Material: A; Object Layer Attributes #1, Attributset-Objekt: Covering; Object Layer Attributes #1, Allright_Bauteil_ID: 1166Wa 0000664055; Object Layer Attributes #1, Abrechnungsart: m²; Object Layer Attributes #1, Objektname: Wand; Pset_CoveringCommon - IsExternal: no; FireRating: -; ThermalTransmittance: 0 W/K/m2; Reference: Reference
a-sh Abschluss Abhangdecke | H2 Ebene +1 | CEILING |  | 1166HWa0000664059 | m² |  |  |  |  |  | Gesamtwand |  |  |  | NEW | AllplanAttributes - Bezeichnung: a-sh Abschluss Abhangdecke; Attributset-Objekt: Covering; Object Layer Attributes #1, 2D Interaktion: yes; Object Layer Attributes #1, Gewerk: Trockenbauarbeiten; Object Layer Attributes #1, Material: A; Object Layer Attributes #1, Attributset-Objekt: Covering; Object Layer Attributes #1, Allright_Bauteil_ID: 1166Wa 0000664060; Object Layer Attributes #1, Abrechnungsart: m²; Object Layer Attributes #1, Objektname: Wand; Pset_CoveringCommon - IsExternal: no; FireRating: -; ThermalTransmittance: 0 W/K/m2; Reference: Reference
a-sh Abschluss Abhangdecke | H2 Ebene +1 | CEILING |  | 1166HWa0000664064 | m² |  |  |  |  |  | Gesamtwand |  |  |  | NEW | AllplanAttributes - Bezeichnung: a-sh Abschluss Abhangdecke; Attributset-Objekt: Covering; Object Layer Attributes #1, 2D Interaktion: yes; Object Layer Attributes #1, Gewerk: Trockenbauarbeiten; Object Layer Attributes #1, Material: A; Object Layer Attributes #1, Attributset-Objekt: Covering; Object Layer Attributes #1, Allright_Bauteil_ID: 1166Wa 0000664065; Object Layer Attributes #1, Abrechnungsart: m²; Object Layer Attributes #1, Objektname: Wand; Pset_CoveringCommon - IsExternal: no; FireRating: -; ThermalTransmittance: 0 W/K/m2; Reference: Reference
a-sh Abschluss Abhangdecke | H2 Ebene +1 | CEILING |  | 1166HWa0000664069 | m² |  |  |  |  |  | Gesamtwand |  |  |  | NEW | AllplanAttributes - Bezeichnung: a-sh Abschluss Abhangdecke; Attributset-Objekt: Covering; Object Layer Attributes #1, 2D Interaktion: yes; Object Layer Attributes #1, Gewerk: Trockenbauarbeiten; Object Layer Attributes #1, Material: A; Object Layer Attributes #1, Attributset-Objekt: Covering; Object Layer Attributes #1, Allright_Bauteil_ID: 1166Wa 0000664070; Object Layer Attributes #1, Abrechnungsart: m²; Object Layer Attributes #1, Objektname: Wand; Pset_CoveringCommon - IsExternal: no; FireRating: -; ThermalTransmittance: 0 W/K/m2; Reference: Reference
a-sh Abschluss Abhangdecke | H2 Ebene +1 | CEILING |  | 1166HWa0000664074 | m² |  |  |  |  |  | Gesamtwand |  |  |  | NEW | AllplanAttributes - Bezeichnung: a-sh Abschluss Abhangdecke; Attributset-Objekt: Covering; Object Layer Attributes #1, 2D Interaktion: yes; Object Layer Attributes #1, Gewerk: Trockenbauarbeiten; Object Layer Attributes #1, Material: A; Object Layer Attributes #1, Attributset-Objekt: Covering; Object Layer Attributes #1, Allright_Bauteil_ID: 1166Wa 0000664075; Object Layer Attributes #1, Abrechnungsart: m²; Object Layer Attributes #1, Objektname: Wand; Pset_CoveringCommon - IsExternal: no; FireRating: -; ThermalTransmittance: 0 W/K/m2; Reference: Reference
a-sh Abschluss Abhangdecke | H2 Ebene +1 | CEILING |  | 1166HWa0000664079 | m² |  |  |  |  |  | Gesamtwand |  |  |  | NEW | AllplanAttributes - Bezeichnung: a-sh Abschluss Abhangdecke; Attributset-Objekt: Covering; Object Layer Attributes #1, 2D Interaktion: yes; Object Layer Attributes #1, Gewerk: Trockenbauarbeiten; Object Layer Attributes #1, Material: A; Object Layer Attributes #1, Attributset-Objekt: Covering; Object Layer Attributes #1, Allright_Bauteil_ID: 1166Wa 0000664080; Object Layer Attributes #1, Abrechnungsart: m²; Object Layer Attributes #1, Objektname: Wand; Pset_CoveringCommon - IsExternal: no; FireRating: -; ThermalTransmittance: 0 W/K/m2; Reference: Reference
a-sh Abschluss Abhangdecke | H2 Ebene +1 | CEILING |  | 1166HWa0000664084 | m² |  |  |  |  |  | Gesamtwand |  |  |  | NEW | AllplanAttributes - Bezeichnung: a-sh Abschluss Abhangdecke; Attributset-Objekt: Covering; Object Layer Attributes #1, 2D Interaktion: yes; Object Layer Attributes #1, Gewerk: Trockenbauarbeiten; Object Layer Attributes #1, Material: A; Object Layer Attributes #1, Attributset-Objekt: Covering; Object Layer Attributes #1, Allright_Bauteil_ID: 1166Wa 0000664085; Object Layer Attributes #1, Abrechnungsart: m²; Object Layer Attributes #1, Objektname: Wand; Pset_CoveringCommon - IsExternal: no; FireRating: -; ThermalTransmittance: 0 W/K/m2; Reference: Reference
a-sh Abschluss Abhangdecke | H2 Ebene +1 | CEILING |  | 1166HWa0000664089 | m² |  |  |  |  |  | Gesamtwand |  |  |  | NEW | AllplanAttributes - Bezeichnung: a-sh Abschluss Abhangdecke; Attributset-Objekt: Covering; Object Layer Attributes #1, 2D Interaktion: yes; Object Layer Attributes #1, Gewerk: Trockenbauarbeiten; Object Layer Attributes #1, Material: A; Object Layer Attributes #1, Attributset-Objekt: Covering; Object Layer Attributes #1, Allright_Bauteil_ID: 1166Wa 0000664090; Object Layer Attributes #1, Abrechnungsart: m²; Object Layer Attributes #1, Objektname: Wand; Pset_CoveringCommon - IsExternal: no; FireRating: -; ThermalTransmittance: 0 W/K/m2; Reference: Reference
a-sh Abschluss Abhangdecke | H2 Ebene +1 | CEILING |  | 1166HWa0000664094 | m² |  |  |  |  |  | Gesamtwand |  |  |  | NEW | AllplanAttributes - Bezeichnung: a-sh Abschluss Abhangdecke; Attributset-Objekt: Covering; Object Layer Attributes #1, 2D Interaktion: yes; Object Layer Attributes #1, Gewerk: Trockenbauarbeiten; Object Layer Attributes #1, Material: A; Object Layer Attributes #1, Attributset-Objekt: Covering; Object Layer Attributes #1, Allright_Bauteil_ID: 1166Wa 0000664095; Object Layer Attributes #1, Abrechnungsart: m²; Object Layer Attributes #1, Objektname: Wand; Pset_CoveringCommon - IsExternal: no; FireRating: -; ThermalTransmittance: 0 W/K/m2; Reference: Reference
a-sh Abschluss Abhangdecke | H2 Ebene +1 | CEILING |  | 1166HWa0000664099 | m² |  |  |  |  |  | Gesamtwand |  |  |  | NEW | AllplanAttributes - Bezeichnung: a-sh Abschluss Abhangdecke; Attributset-Objekt: Covering; Object Layer Attributes #1, 2D Interaktion: yes; Object Layer Attributes #1, Gewerk: Trockenbauarbeiten; Object Layer Attributes #1, Material: A; Object Layer Attributes #1, Attributset-Objekt: Covering; Object Layer Attributes #1, Allright_Bauteil_ID: 1166Wa 0000664100; Object Layer Attributes #1, Abrechnungsart: m²; Object Layer Attributes #1, Objektname: Wand; Pset_CoveringCommon - IsExternal: no; FireRating: -; ThermalTransmittance: 0 W/K/m2; Reference: Reference
a-sh Abschluss Abhangdecke | H2 Ebene +1 | CEILING |  | 1166HWa0000664104 | m² |  |  |  |  |  | Gesamtwand |  |  |  | NEW | AllplanAttributes - Bezeichnung: a-sh Abschluss Abhangdecke; Attributset-Objekt: Covering; Object Layer Attributes #1, 2D Interaktion: yes; Object Layer Attributes #1, Gewerk: Trockenbauarbeiten; Object Layer Attributes #1, Material: A; Object Layer Attributes #1, Attributset-Objekt: Covering; Object Layer Attributes #1, Allright_Bauteil_ID: 1166Wa 0000664105; Object Layer Attributes #1, Abrechnungsart: m²; Object Layer Attributes #1, Objektname: Wand; Pset_CoveringCommon - IsExternal: no; FireRating: -; ThermalTransmittance: 0 W/K/m2; Reference: Reference
a-sh Abschluss Abhangdecke | H2 Ebene +1 | CEILING | FP2 | 1166HWa0000664109 | m² |  |  |  |  |  | Gesamtwand |  |  |  | NEW | AllplanAttributes - Bezeichnung: a-sh Abschluss Abhangdecke; Attributset-Objekt: Covering; Object Layer Attributes #1, 2D Interaktion: yes; Object Layer Attributes #1, Gewerk: Trockenbauarbeiten; Object Layer Attributes #1, Material: A; Object Layer Attributes #1, Attributset-Objekt: Covering; Object Layer Attributes #1, Allright_Bauteil_ID: 1166Wa 0000664110; Object Layer Attributes #1, Abrechnungsart: m²; Object Layer Attributes #1, Objektname: Wand; Pset_CoveringCommon - IsExternal: no; FireRating: -; ThermalTransmittance: 0 W/K/m2; Reference: Reference
a-sh Abschluss Abhangdecke | H2 Ebene +1 | CEILING |  | 1166HWa0000664114 | m² |  |  |  |  |  | Gesamtwand |  |  |  | NEW | AllplanAttributes - Bezeichnung: a-sh Abschluss Abhangdecke; Attributset-Objekt: Covering; Object Layer Attributes #1, 2D Interaktion: yes; Object Layer Attributes #1, Gewerk: Trockenbauarbeiten; Object Layer Attributes #1, Material: A; Object Layer Attributes #1, Attributset-Objekt: Covering; Object Layer Attributes #1, Allright_Bauteil_ID: 1166Wa 0000664115; Object Layer Attributes #1, Abrechnungsart: m²; Object Layer Attributes #1, Objektname: Wand; Pset_CoveringCommon - IsExternal: no; FireRating: -; ThermalTransmittance: 0 W/K/m2; Reference: Reference
a-sh Abschluss Abhangdecke | H2 Ebene +1 | CEILING |  | 1166HWa0000664119 | m² |  |  |  |  |  | Gesamtwand |  |  |  | NEW | AllplanAttributes - Bezeichnung: a-sh Abschluss Abhangdecke; Attributset-Objekt: Covering; Object Layer Attributes #1, 2D Interaktion: yes; Object Layer Attributes #1, Gewerk: Trockenbauarbeiten; Object Layer Attributes #1, Material: A; Object Layer Attributes #1, Attributset-Objekt: Covering; Object Layer Attributes #1, Allright_Bauteil_ID: 1166Wa 0000664120; Object Layer Attributes #1, Abrechnungsart: m²; Object Layer Attributes #1, Objektname: Wand; Pset_CoveringCommon - IsExternal: no; FireRating: -; ThermalTransmittance: 0 W/K/m2; Reference: Reference
a-sh Abschluss Abhangdecke | H2 Ebene +1 | CEILING |  | 1166HWa0000664124 | m² |  |  |  |  |  | Gesamtwand |  |  |  | NEW | AllplanAttributes - Bezeichnung: a-sh Abschluss Abhangdecke; Attributset-Objekt: Covering; Object Layer Attributes #1, 2D Interaktion: yes; Object Layer Attributes #1, Gewerk: Trockenbauarbeiten; Object Layer Attributes #1, Material: A; Object Layer Attributes #1, Attributset-Objekt: Covering; Object Layer Attributes #1, Allright_Bauteil_ID: 1166Wa 0000664125; Object Layer Attributes #1, Abrechnungsart: m²; Object Layer Attributes #1, Objektname: Wand; Pset_CoveringCommon - IsExternal: no; FireRating: -; ThermalTransmittance: 0 W/K/m2; Reference: Reference
a-sh Abschluss Abhangdecke | H2 Ebene +1 | CEILING |  | 1166HWa0000664129 | m² |  |  |  |  |  | Gesamtwand |  |  |  | NEW | AllplanAttributes - Bezeichnung: a-sh Abschluss Abhangdecke; Attributset-Objekt: Covering; Object Layer Attributes #1, 2D Interaktion: yes; Object Layer Attributes #1, Gewerk: Trockenbauarbeiten; Object Layer Attributes #1, Material: A; Object Layer Attributes #1, Attributset-Objekt: Covering; Object Layer Attributes #1, Allright_Bauteil_ID: 1166Wa 0000664130; Object Layer Attributes #1, Abrechnungsart: m²; Object Layer Attributes #1, Objektname: Wand; Pset_CoveringCommon - IsExternal: no; FireRating: -; ThermalTransmittance: 0 W/K/m2; Reference: Reference
a-sh Abschluss Abhangdecke | H2 Ebene +1 | CEILING |  | 1166HWa0000664134 | m² |  |  |  |  |  | Gesamtwand |  |  |  | NEW | AllplanAttributes - Bezeichnung: a-sh Abschluss Abhangdecke; Attributset-Objekt: Covering; Object Layer Attributes #1, 2D Interaktion: yes; Object Layer Attributes #1, Gewerk: Trockenbauarbeiten; Object Layer Attributes #1, Material: A; Object Layer Attributes #1, Attributset-Objekt: Covering; Object Layer Attributes #1, Allright_Bauteil_ID: 1166Wa 0000664135; Object Layer Attributes #1, Abrechnungsart: m²; Object Layer Attributes #1, Objektname: Wand; Pset_CoveringCommon - IsExternal: no; FireRating: -; ThermalTransmittance: 0 W/K/m2; Reference: Reference
a-sh Abschluss Abhangdecke | H2 Ebene +1 | CEILING |  | 1166HWa0000664139 | m² |  |  |  |  |  | Gesamtwand |  |  |  | NEW | AllplanAttributes - Bezeichnung: a-sh Abschluss Abhangdecke; Attributset-Objekt: Covering; Object Layer Attributes #1, 2D Interaktion: yes; Object Layer Attributes #1, Gewerk: Trockenbauarbeiten; Object Layer Attributes #1, Material: A; Object Layer Attributes #1, Attributset-Objekt: Covering; Object Layer Attributes #1, Allright_Bauteil_ID: 1166Wa 0000664140; Object Layer Attributes #1, Abrechnungsart: m²; Object Layer Attributes #1, Objektname: Wand; Pset_CoveringCommon - IsExternal: no; FireRating: -; ThermalTransmittance: 0 W/K/m2; Reference: Reference
a-sh Abschluss Abhangdecke | H2 Ebene +1 | CEILING | FP2 | 1166HWa0000664144 | m² |  |  |  |  |  | Gesamtwand |  |  |  | NEW | AllplanAttributes - Bezeichnung: a-sh Abschluss Abhangdecke; Attributset-Objekt: Covering; Object Layer Attributes #1, 2D Interaktion: yes; Object Layer Attributes #1, Gewerk: Trockenbauarbeiten; Object Layer Attributes #1, Material: A; Object Layer Attributes #1, Tragendes Bauteil: no; Object Layer Attributes #1, Attributset-Objekt: Covering; Object Layer Attributes #1, Allright_Bauteil_ID: 1166Wa 0000664145; Object Layer Attributes #1, Abrechnungsart: m²; Object Layer Attributes #1, Objektname: Wand; Pset_CoveringCommon - IsExternal: no; FireRating: -; ThermalTransmittance: 0 W/K/m2; Reference: Reference
a-sh Abschluss Abhangdecke | H2 Ebene +1 | CEILING |  | 1166HWa0000664149 | m² |  |  |  |  |  | Gesamtwand |  |  |  | NEW | AllplanAttributes - Bezeichnung: a-sh Abschluss Abhangdecke; Attributset-Objekt: Covering; Object Layer Attributes #1, 2D Interaktion: yes; Object Layer Attributes #1, Gewerk: Trockenbauarbeiten; Object Layer Attributes #1, Material: A; Object Layer Attributes #1, Tragendes Bauteil: no; Object Layer Attributes #1, Attributset-Objekt: Covering; Object Layer Attributes #1, Allright_Bauteil_ID: 1166Wa 0000664150; Object Layer Attributes #1, Abrechnungsart: m²; Object Layer Attributes #1, Objektname: Wand; Pset_CoveringCommon - IsExternal: no; FireRating: -; ThermalTransmittance: 0 W/K/m2; Reference: Reference
a-sh Abschluss Abhangdecke | H2 Ebene +1 | CEILING |  | 1166HWa0000664159 | m² |  |  |  |  |  | Gesamtwand |  |  |  | NEW | AllplanAttributes - Bezeichnung: a-sh Abschluss Abhangdecke; Attributset-Objekt: Covering; Object Layer Attributes #1, 2D Interaktion: yes; Object Layer Attributes #1, Gewerk: Trockenbauarbeiten; Object Layer Attributes #1, Material: A; Object Layer Attributes #1, Tragendes Bauteil: no; Object Layer Attributes #1, Attributset-Objekt: Covering; Object Layer Attributes #1, Allright_Bauteil_ID: 1166Wa 0000664160; Object Layer Attributes #1, Abrechnungsart: m²; Object Layer Attributes #1, Objektname: Wand; Pset_CoveringCommon - IsExternal: no; FireRating: -; ThermalTransmittance: 0 W/K/m2; Reference: Reference
a-sh Abschluss Abhangdecke | H2 Ebene +1 | CEILING |  | 1166HWa0000664179 | m² |  |  |  |  |  | Gesamtwand |  |  |  | NEW | AllplanAttributes - Bezeichnung: a-sh Abschluss Abhangdecke; Attributset-Objekt: Covering; Object Layer Attributes #1, 2D Interaktion: yes; Object Layer Attributes #1, Gewerk: Trockenbauarbeiten; Object Layer Attributes #1, Material: A; Object Layer Attributes #1, Tragendes Bauteil: no; Object Layer Attributes #1, Attributset-Objekt: Covering; Object Layer Attributes #1, Allright_Bauteil_ID: 1166Wa 0000664180; Object Layer Attributes #1, Abrechnungsart: m²; Object Layer Attributes #1, Objektname: Wand; Pset_CoveringCommon - IsExternal: no; FireRating: -; ThermalTransmittance: 0 W/K/m2; Reference: Reference
a-sh Abschluss Abhangdecke | H2 Ebene +1 | CEILING |  | 1166HWa0000664184 | m² |  |  |  |  |  | Gesamtwand |  |  |  | NEW | AllplanAttributes - Bezeichnung: a-sh Abschluss Abhangdecke; Attributset-Objekt: Covering; Object Layer Attributes #1, 2D Interaktion: yes; Object Layer Attributes #1, Gewerk: Trockenbauarbeiten; Object Layer Attributes #1, Material: A; Object Layer Attributes #1, Tragendes Bauteil: no; Object Layer Attributes #1, Attributset-Objekt: Covering; Object Layer Attributes #1, Allright_Bauteil_ID: 1166Wa 0000664185; Object Layer Attributes #1, Abrechnungsart: m²; Object Layer Attributes #1, Objektname: Wand; Pset_CoveringCommon - IsExternal: no; FireRating: -; ThermalTransmittance: 0 W/K/m2; Reference: Reference
a-sh Abschluss Abhangdecke | H2 Ebene +1 | CEILING |  | 1166HWa0000664194 | m² |  |  |  |  |  | Gesamtwand |  |  |  | NEW | AllplanAttributes - Bezeichnung: a-sh Abschluss Abhangdecke; Attributset-Objekt: Covering; Object Layer Attributes #1, 2D Interaktion: yes; Object Layer Attributes #1, Gewerk: Trockenbauarbeiten; Object Layer Attributes #1, Material: A; Object Layer Attributes #1, Tragendes Bauteil: no; Object Layer Attributes #1, Attributset-Objekt: Covering; Object Layer Attributes #1, Allright_Bauteil_ID: 1166Wa 0000664195; Object Layer Attributes #1, Abrechnungsart: m²; Object Layer Attributes #1, Objektname: Wand; Pset_CoveringCommon - IsExternal: no; FireRating: -; ThermalTransmittance: 0 W/K/m2; Reference: Reference
a-sh Abschluss Abhangdecke | H2 Ebene +1 | CEILING |  | 1166HWa0000664206 | m² |  |  |  |  |  | Gesamtwand |  |  |  | NEW | AllplanAttributes - Bezeichnung: a-sh Abschluss Abhangdecke; Attributset-Objekt: Covering; Object Layer Attributes #1, 2D Interaktion: yes; Object Layer Attributes #1, Gewerk: Trockenbauarbeiten; Object Layer Attributes #1, Material: A; Object Layer Attributes #1, Tragendes Bauteil: no; Object Layer Attributes #1, Attributset-Objekt: Covering; Object Layer Attributes #1, Allright_Bauteil_ID: 1166Wa 0000664207; Object Layer Attributes #1, Abrechnungsart: m²; Object Layer Attributes #1, Objektname: Wand; Pset_CoveringCommon - IsExternal: no; FireRating: -; ThermalTransmittance: 0 W/K/m2; Reference: Reference
a-sh Abschluss Abhangdecke | H2 Ebene +1 | CEILING |  | 1166HWa0000664215 | m² |  |  |  |  |  | Gesamtwand |  |  |  | NEW | AllplanAttributes - Bezeichnung: a-sh Abschluss Abhangdecke; Attributset-Objekt: Covering; Object Layer Attributes #1, 2D Interaktion: yes; Object Layer Attributes #1, Gewerk: Trockenbauarbeiten; Object Layer Attributes #1, Material: A; Object Layer Attributes #1, Tragendes Bauteil: no; Object Layer Attributes #1, Attributset-Objekt: Covering; Object Layer Attributes #1, Allright_Bauteil_ID: 1166Wa 0000664216; Object Layer Attributes #1, Abrechnungsart: m²; Object Layer Attributes #1, Objektname: Wand; Pset_CoveringCommon - IsExternal: no; FireRating: -; ThermalTransmittance: 0 W/K/m2; Reference: Reference
Fliesen | WUN-H2-E01-012b | FLOORING | Fl1 0.15 m | 1166Bfl0000033243/01 | m² | Bodenbelagsarbeiten | 1 | 0.15 | 0 | 1 | Bodenfläche | Fl1 | 0 | 0 | NEW | AllplanAttributes - Bezeichnung: Fliesen; Raumnr. Bauherr: 2.11_A2_02; ash B_Aufbau: B10; ash B_Rutschhemmung: R10
Gipsfaserplatten 2-lagig (BSK) | WUN-H2-E01-012b | CEILING | layer 0.036 m | 1166Dfl0000033242/01 | m² | Trockenbauarbeiten | 1 | 0.036 | 0 | 1 | Deckenfläche |  | 0 | 0 | NEW | 2.5 | AllplanAttributes - Bezeichnung: Gipsfaserplatten 2-lagig (BSK); RoomName: WC Krisenzimmer
Gipsfaserplatten 2-lagig (BSK) | WUN-H2-E01-012b | CEILING | Installationshöhe 0.764 m | 1166Dfl0000033242/02 | m² | Trockenbauarbeiten | 2 | 0.764 | 0 | 1 | Bekleidung | Installationshöhe | 0 | 0 | NEW | 2.5 | AllplanAttributes - ash_lichte Raumhöhe: 2.500000; OKFF: 0; RoomName: WC Krisenzimmer
Gipskarton, imprägniert | WUN-H2-E01-012b | CEILING | B 0.1 m | 1166Dfl0000033242/03 | m² | Trockenbauarbeiten | 3 | 0.1 | 0 | 1 | Bekleidung | B | 0 | 0 | NEW | 2.5 | AllplanAttributes - Bezeichnung: Gipskarton, imprägniert; ash_lichte Raumhöhe: 2.500000; OKFF: 0; RoomName: WC Krisenzimmer; Pset_CoveringCommon - AcousticRating: -
Gipsfaserplatten 2-lagig (BSK) | WUN-H2-E01-012b | CEILING | D1 0.001 m | 1166Dfl0000033242/04 | m² | Maler- und Lackierarbeiten | 4 | 0.001 | 0 | 1 | Bekleidung | D1 | 0 | 0 | NEW | 2.5 | AllplanAttributes - ash_lichte Raumhöhe: 2.500000; OKFF: 0; RoomName: WC Krisenzimmer
Fliesen | WUN-H2-E01-052b | FLOORING | Fl1 0.15 m | 1166Bfl0000033842/01 | m² | Bodenbelagsarbeiten | 1 | 0.15 | 0 | 1 | Bodenfläche | Fl1 | 0 | 0 | NEW | AllplanAttributes - Bezeichnung: Fliesen; Raumnr. Bauherr: 2.11_A2_02; ash B_Aufbau: B10; ash B_Rutschhemmung: R10
Gipsfaserplatten 2-lagig (BSK) | WUN-H2-E01-052b | CEILING | layer 0.036 m | 1166Dfl0000033843/01 | m² | Trockenbauarbeiten | 1 | 0.036 | 0 | 1 | Deckenfläche |  | 0 | 0 | NEW | 2.5 | AllplanAttributes - Bezeichnung: Gipsfaserplatten 2-lagig (BSK); RoomName: WC Pat.
Gipsfaserplatten 2-lagig (BSK) | WUN-H2-E01-052b | CEILING | Installationshöhe 0.764 m | 1166Dfl0000033843/02 | m² | Trockenbauarbeiten | 2 | 0.764 | 0 | 1 | Bekleidung | Installationshöhe | 0 | 0 | NEW | 2.5 | AllplanAttributes - ash_lichte Raumhöhe: 2.500000; OKFF: 0; RoomName: WC Pat.
Gipskarton, imprägniert | WUN-H2-E01-052b | CEILING | B 0.1 m | 1166Dfl0000033843/03 | m² | Trockenbauarbeiten | 3 | 0.1 | 0 | 1 | Bekleidung | B | 0 | 0 | NEW | 2.5 | AllplanAttributes - Bezeichnung: Gipskarton, imprägniert; ash_lichte Raumhöhe: 2.500000; OKFF: 0; RoomName: WC Pat.; Pset_CoveringCommon - AcousticRating: -
Gipsfaserplatten 2-lagig (BSK) | WUN-H2-E01-052b | CEILING | D1 0.001 m | 1166Dfl0000033843/04 | m² | Maler- und Lackierarbeiten | 4 | 0.001 | 0 | 1 | Bekleidung | D1 | 0 | 0 | NEW | 2.5 | AllplanAttributes - ash_lichte Raumhöhe: 2.500000; OKFF: 0; RoomName: WC Pat.
a-sh Wandbelag | WUN-H2-E01-052b | CLADDING | 65 0.01 m | 1166Sfl0000667737/01 | m² | Maler- und Lackierarbeiten | 1 | 0.01 | 0 | 1 | Seitenfläche | 65 | 100 | 3000 | NEW | AllplanAttributes - Bezeichnung: a-sh Wandbelag; Attributset-Objekt: Covering
 | WUN-H2-E01-052b | CLADDING | 50 0.001 m | 1166Sfl0000668131/01 | m² | Maler- und Lackierarbeiten | 1 | 0.001 | 0 | 1 | Seitenfläche | 50 | 150 | 2500 | NEW
Fliesen | WUN-H2-E01-052a | FLOORING | Fl1 0.15 m | 1166Bfl0000033831/01 | m² | Bodenbelagsarbeiten | 1 | 0.15 | 0 | 1 | Bodenfläche | Fl1 | 0 | 0 | NEW | AllplanAttributes - Bezeichnung: Fliesen; Raumnr. Bauherr: 2.11_A2_02; ash B_Aufbau: B10; ash B_Rutschhemmung: R10
Gipsfaserplatten 2-lagig (BSK) | WUN-H2-E01-052a | CEILING | layer 0.036 m | 1166Dfl0000033832/01 | m² | Trockenbauarbeiten | 1 | 0.036 | 0 | 1 | Deckenfläche |  | 0 | 0 | NEW | 2.5 | AllplanAttributes - Bezeichnung: Gipsfaserplatten 2-lagig (BSK); RoomName: WC Pat.
Gipsfaserplatten 2-lagig (BSK) | WUN-H2-E01-052a | CEILING | Installationshöhe 0.764 m | 1166Dfl0000033832/02 | m² | Trockenbauarbeiten | 2 | 0.764 | 0 | 1 | Bekleidung | Installationshöhe | 0 | 0 | NEW | 2.5 | AllplanAttributes - ash_lichte Raumhöhe: 2.500000; OKFF: 0; RoomName: WC Pat.
Gipskarton, imprägniert | WUN-H2-E01-052a | CEILING | B 0.1 m | 1166Dfl0000033832/03 | m² | Trockenbauarbeiten | 3 | 0.1 | 0 | 1 | Bekleidung | B | 0 | 0 | NEW | 2.5 | AllplanAttributes - Bezeichnung: Gipskarton, imprägniert; ash_lichte Raumhöhe: 2.500000; OKFF: 0; RoomName: WC Pat.; Pset_CoveringCommon - AcousticRating: -
Gipsfaserplatten 2-lagig (BSK) | WUN-H2-E01-052a | CEILING | D1 0.001 m | 1166Dfl0000033832/04 | m² | Maler- und Lackierarbeiten | 4 | 0.001 | 0 | 1 | Bekleidung | D1 | 0 | 0 | NEW | 2.5 | AllplanAttributes - ash_lichte Raumhöhe: 2.500000; OKFF: 0; RoomName: WC Pat.
a-sh Wandbelag | WUN-H2-E01-052a | CLADDING | 65 0.01 m | 1166Sfl0000667934/01 | m² | Maler- und Lackierarbeiten | 1 | 0.01 | 0 | 1 | Seitenfläche | 65 | 100 | 3000 | NEW | AllplanAttributes - Bezeichnung: a-sh Wandbelag; Attributset-Objekt: Covering
 | WUN-H2-E01-052a | CLADDING | 50 0.001 m | 1166Sfl0000668328/01 | m² | Maler- und Lackierarbeiten | 1 | 0.001 | 0 | 1 | Seitenfläche | 50 | 150 | 2500 | NEW
 | WUN-H2-E01-L01 | CEILING | Installationshöhe 0.18 m | 1166Dfl0000439052/01 | m² | Trockenbauarbeiten | 1 | 0.18 | 0 | 1 | Bekleidung | Installationshöhe | 0 | 0 | NEW | 3.1 | AllplanAttributes - ash_lichte Raumhöhe: (7070-180+45)/1000-3.75; RoomName: Sprechzimmer; Pset_CoveringCommon - AcousticRating: -
 | WUN-H2-E01-L01 | CEILING | - 0.045 m | 1166Dfl0000439052/02 | m² | Trockenbauarbeiten | 2 | 0.045 | 0 | 1 | Bekleidung | - | 0 | 0 | NEW | 3.1 | AllplanAttributes - ash_lichte Raumhöhe: (7070-180+45)/1000-3.75; RoomName: Sprechzimmer; Pset_CoveringCommon - AcousticRating: -
Unterbodenaufbau (Stelzen + Estrich) | WUN-H2-E01-L01 | FLOORING | layer 0.25 m | 1166Bfl0000439053/01 | m² | Bodenbelagsarbeiten | 1 | 0.25 | 0 | 1 | Bodenfläche |  | 0 | 0 | NEW | AllplanAttributes - Bezeichnung: Unterbodenaufbau (Stelzen + Estrich)
Feinsteinzeugplatten 40x40x3 | WUN-H2-E01-L01 | FLOORING | FP2 0.03 m | 1166Bfl0000439053/02 | m² | Bodenbelagsarbeiten | 2 | 0.03 | 0 | 1 | Bodenfläche | FP2 | 0 | 0 | NEW | AllplanAttributes - Bezeichnung: Feinsteinzeugplatten 40x40x3; Raumnr. Bauherr: 2.11_A2_02
 | WUN-H2-E01-L02 | CEILING | Installationshöhe 0.18 m | 1166Dfl0000439084/01 | m² | Trockenbauarbeiten | 1 | 0.18 | 0 | 1 | Bekleidung | Installationshöhe | 0 | 0 | NEW | 3.1 | AllplanAttributes - ash_lichte Raumhöhe: (7070-180+45)/1000-3.75; RoomName: Sprechzimmer; Pset_CoveringCommon - AcousticRating: -
 | WUN-H2-E01-L02 | CEILING | - 0.045 m | 1166Dfl0000439084/02 | m² | Trockenbauarbeiten | 2 | 0.045 | 0 | 1 | Bekleidung | - | 0 | 0 | NEW | 3.1 | AllplanAttributes - ash_lichte Raumhöhe: (7070-180+45)/1000-3.75; RoomName: Sprechzimmer; Pset_CoveringCommon - AcousticRating: -
Unterbodenaufbau (Stelzen + Estrich) | WUN-H2-E01-L02 | FLOORING | layer 0.25 m | 1166Bfl0000439085/01 | m² | Bodenbelagsarbeiten | 1 | 0.25 | 0 | 1 | Bodenfläche |  | 0 | 0 | NEW | AllplanAttributes - Bezeichnung: Unterbodenaufbau (Stelzen + Estrich)
Feinsteinzeugplatten 40x40x3 | WUN-H2-E01-L02 | FLOORING | FP2 0.03 m | 1166Bfl0000439085/02 | m² | Bodenbelagsarbeiten | 2 | 0.03 | 0 | 1 | Bodenfläche | FP2 | 0 | 0 | NEW | AllplanAttributes - Bezeichnung: Feinsteinzeugplatten 40x40x3; Raumnr. Bauherr: 2.11_A2_02
Fliesen | WUN-H2-E01-079 | FLOORING | Fl1 0.15 m | 1166Bfl0000034275/01 | m² | Bodenbelagsarbeiten | 1 | 0.15 | 0 | 1 | Bodenfläche | Fl1 | 0 | 0 | NEW | AllplanAttributes - Bezeichnung: Fliesen; Raumnr. Bauherr: 2.11_A2_02; ash B_Aufbau: B10; ash B_Rutschhemmung: R10
Gipsfaserplatten 2-lagig (BSK) | WUN-H2-E01-079 | CEILING | layer 0.036 m | 1166Dfl0000034274/01 | m² | Trockenbauarbeiten | 1 | 0.036 | 0 | 1 | Deckenfläche |  | 0 | 0 | NEW | 2.5 | AllplanAttributes - Bezeichnung: Gipsfaserplatten 2-lagig (BSK); RoomName: WC Pers.
Gipsfaserplatten 2-lagig (BSK) | WUN-H2-E01-079 | CEILING | Installationshöhe 0.764 m | 1166Dfl0000034274/02 | m² | Trockenbauarbeiten | 2 | 0.764 | 0 | 1 | Bekleidung | Installationshöhe | 0 | 0 | NEW | 2.5 | AllplanAttributes - ash_lichte Raumhöhe: (7150-36+764+100)/1000-3.75; OKFF: 0; RoomName: WC Pers.
Rasterdecke | WUN-H2-E01-079 | CEILING | E3 0.1 m | 1166Dfl0000034274/03 | m² | Trockenbauarbeiten | 3 | 0.1 | 0 | 1 | Bekleidung | E3 | 0 | 0 | NEW | 2.5 | AllplanAttributes - Bezeichnung: Rasterdecke; ash_lichte Raumhöhe: (7150-36+764+100)/1000-3.75; OKFF: 0; RoomName: WC Pers.; Pset_CoveringCommon - AcousticRating: -
a-sh Wandbelag | WUN-H2-E01-079 | CLADDING | 65 0.01 m | 1166Sfl0000667373/01 | m² | Maler- und Lackierarbeiten | 1 | 0.01 | 0 | 1 | Seitenfläche | 65 | 100 | 3000 | NEW | AllplanAttributes - Bezeichnung: a-sh Wandbelag; Attributset-Objekt: Covering
 | WUN-H2-E01-079 | CLADDING | 50 0.001 m | 1166Sfl0000667594/01 | m² | Maler- und Lackierarbeiten | 1 | 0.001 | 0 | 1 | Seitenfläche | 50 | 150 | 2500 | NEW
Fliesen | WUN-H2-E01-080 | FLOORING | Fl1 0.15 m | 1166Bfl0000034286/01 | m² | Bodenbelagsarbeiten | 1 | 0.15 | 0 | 1 | Bodenfläche | Fl1 | 0 | 0 | NEW | AllplanAttributes - Bezeichnung: Fliesen; Raumnr. Bauherr: 2.11_A2_02; ash B_Aufbau: B10; ash B_Rutschhemmung: R10
Gipsfaserplatten 2-lagig (BSK) | WUN-H2-E01-080 | CEILING | layer 0.036 m | 1166Dfl0000034285/01 | m² | Trockenbauarbeiten | 1 | 0.036 | 0 | 1 | Deckenfläche |  | 0 | 0 | NEW | 2.5 | AllplanAttributes - Bezeichnung: Gipsfaserplatten 2-lagig (BSK); RoomName: WC Pers.
Gipsfaserplatten 2-lagig (BSK) | WUN-H2-E01-080 | CEILING | Installationshöhe 0.764 m | 1166Dfl0000034285/02 | m² | Trockenbauarbeiten | 2 | 0.764 | 0 | 1 | Bekleidung | Installationshöhe | 0 | 0 | NEW | 2.5 | AllplanAttributes - ash_lichte Raumhöhe: (7150-36+764+100)/1000-3.75; OKFF: 0; RoomName: WC Pers.
Rasterdecke | WUN-H2-E01-080 | CEILING | E3 0.1 m | 1166Dfl0000034285/03 | m² | Trockenbauarbeiten | 3 | 0.1 | 0 | 1 | Bekleidung | E3 | 0 | 0 | NEW | 2.5 | AllplanAttributes - Bezeichnung: Rasterdecke; ash_lichte Raumhöhe: (7150-36+764+100)/1000-3.75; OKFF: 0; RoomName: WC Pers.; Pset_CoveringCommon - AcousticRating: -
 | WUN-H2-E01-080 | CLADDING | 50 0.001 m | 1166Sfl0000667663/01 | m² | Maler- und Lackierarbeiten | 1 | 0.001 | 0 | 1 | Seitenfläche | 50 | 150 | 2500 | NEW
a-sh Wandbelag | WUN-H2-E01-080 | CLADDING | 65 0.01 m | 1166Sfl0000667442/01 | m² | Maler- und Lackierarbeiten | 1 | 0.01 | 0 | 1 | Seitenfläche | 65 | 100 | 3000 | NEW | AllplanAttributes - Bezeichnung: a-sh Wandbelag; Attributset-Objekt: Covering
Acrovyn | WUN-H2-E01-041 | CLADDING | 84 0.001 m | 1166Sfl0000220350/02 | m² | Maler- und Lackierarbeiten | 2 | 0.001 | 0 | 1 | Seitenfläche | 84 | 0 | 0 | NEW | AllplanAttributes - Bezeichnung: Acrovyn
Acrovyn | WUN-H2-E01-041 | CLADDING | 84 0.001 m | 1166Sfl0000220342/02 | m² | Maler- und Lackierarbeiten | 2 | 0.001 | 0 | 1 | Seitenfläche | 84 | 0 | 0 | NEW | AllplanAttributes - Bezeichnung: Acrovyn
PVC Bahnenware Holzoptik | WUN-H2-E01-041 | FLOORING | Ku1 0.15 m | 1166Bfl0000033538/01 | m² | Bodenbelagsarbeiten | 1 | 0.15 | 0 | 1 | Bodenfläche | Ku1 | 0 | 0 | NEW | AllplanAttributes - Bezeichnung: PVC Bahnenware Holzoptik; Raumnr. Bauherr: 2.11_A2_02; ash B_Aufbau: B9; ash B_Rutschhemmung: R9
 | WUN-H2-E01-041 | CLADDING | 49 0.001 m | 1166Sfl0000664512/01 | m² | Maler- und Lackierarbeiten | 1 | 0.001 | 0 | 1 | Seitenfläche | 49 | 150 | 3150 | NEW
Gipsfaserplatten 2-lagig (BSK) | WUN-H2-E01-041 | CEILING | layer 0.036 m | 1166Dfl0000033539/01 | m² | Trockenbauarbeiten | 1 | 0.036 | 0 | 1 | Deckenfläche |  | 0 | 0 | NEW | 3.15 | AllplanAttributes - Bezeichnung: Gipsfaserplatten 2-lagig (BSK); RoomName: Doppelzimmer
Gipsfaserplatten 2-lagig (BSK) | WUN-H2-E01-041 | CEILING | Installationshöhe 0.114 m | 1166Dfl0000033539/02 | m² | Trockenbauarbeiten | 2 | 0.114 | 0 | 1 | Bekleidung | Installationshöhe | 0 | 0 | NEW | 3.15 | AllplanAttributes - ash_lichte Raumhöhe: 3.150000; RoomName: Doppelzimmer; Pset_CoveringCommon - AcousticRating: -
Gipsfaserplatten 2-lagig (BSK) | WUN-H2-E01-041 | CEILING | A1 0.1 m | 1166Dfl0000033539/03 | m² | Trockenbauarbeiten | 3 | 0.1 | 0 | 1 | Bekleidung | A1 | 0 | 0 | NEW | 3.15 | AllplanAttributes - ash_lichte Raumhöhe: 3.150000; RoomName: Doppelzimmer; Pset_CoveringCommon - AcousticRating: -
Gipsfaserplatten 2-lagig (BSK) | WUN-H2-E01-041 | CEILING | D1 0.001 m | 1166Dfl0000033539/04 | m² | Maler- und Lackierarbeiten | 4 | 0.001 | 0 | 1 | Bekleidung | D1 | 0 | 0 | NEW | 3.15 | AllplanAttributes - ash_lichte Raumhöhe: 3.150000; RoomName: Doppelzimmer
Gipsfaserplatten 2-lagig (BSK) | WUN-H2-E01-041 | CEILING | layer 0.036 m | 1166Dfl0000033549/01 | m² | Trockenbauarbeiten | 1 | 0.036 | 0 | 1 | Deckenfläche |  | 0 | 0 | NEW | 2.5 | AllplanAttributes - Bezeichnung: Gipsfaserplatten 2-lagig (BSK); RoomName: Ruheraum
Gipsfaserplatten 2-lagig (BSK) | WUN-H2-E01-041 | CEILING | Installationshöhe 0.764 m | 1166Dfl0000033549/02 | m² | Trockenbauarbeiten | 2 | 0.764 | 0 | 1 | Bekleidung | Installationshöhe | 0 | 0 | NEW | 2.5 | AllplanAttributes - ash_lichte Raumhöhe: 2.500000; OKFF: 0; RoomName: Ruheraum
Gipsfaserplatten 2-lagig (BSK) | WUN-H2-E01-041 | CEILING | A1 0.1 m | 1166Dfl0000033549/03 | m² | Trockenbauarbeiten | 3 | 0.1 | 0 | 1 | Bekleidung | A1 | 0 | 0 | NEW | 2.5 | AllplanAttributes - ash_lichte Raumhöhe: 2.500000; OKFF: 0; RoomName: Ruheraum; Pset_CoveringCommon - AcousticRating: -
Gipsfaserplatten 2-lagig (BSK) | WUN-H2-E01-041 | CEILING | D1 0.001 m | 1166Dfl0000033549/04 | m² | Maler- und Lackierarbeiten | 4 | 0.001 | 0 | 1 | Bekleidung | D1 | 0 | 0 | NEW | 2.5 | AllplanAttributes - ash_lichte Raumhöhe: 2.500000; OKFF: 0; RoomName: Ruheraum
Fliesen Mosaik | WUN-H2-E01-041a | FLOORING | Fl2 0.15 m | 1166Bfl0000489404/01 | m² | Bodenbelagsarbeiten | 1 | 0.15 | 0 | 1 | Bodenfläche | Fl2 | 0 | 0 | NEW | AllplanAttributes - Bezeichnung: Fliesen Mosaik; Raumnr. Bauherr: 2.11_A2_02; ash B_Aufbau: B11; ash B_Rutschhemmung: R10; ash B_Bewertungsgruppe Barfußbereich: B
Fliesen | WUN-H2-E01-041a | FLOORING | Fl1 0.15 m | 1166Bfl0000033706/01 | m² | Bodenbelagsarbeiten | 1 | 0.15 | 0 | 1 | Bodenfläche | Fl1 | 0 | 0 | NEW | AllplanAttributes - Bezeichnung: Fliesen; Raumnr. Bauherr: 2.11_A2_02; ash B_Aufbau: B10; ash B_Rutschhemmung: R10
 | WUN-H2-E01-041a | CLADDING | 50 0.001 m | 1166Sfl0000664510/01 | m² | Maler- und Lackierarbeiten | 1 | 0.001 | 0 | 1 | Seitenfläche | 50 | 150 | 2500 | NEW
Gipsfaserplatten 2-lagig (BSK) | WUN-H2-E01-041a | CEILING | layer 0.036 m | 1166Dfl0000033707/01 | m² | Trockenbauarbeiten | 1 | 0.036 | 0 | 1 | Deckenfläche |  | 0 | 0 | NEW | 2.5 | AllplanAttributes - Bezeichnung: Gipsfaserplatten 2-lagig (BSK); RoomName: Nasszelle DZ
Gipsfaserplatten 2-lagig (BSK) | WUN-H2-E01-041a | CEILING | Installationshöhe 0.764 m | 1166Dfl0000033707/02 | m² | Trockenbauarbeiten | 2 | 0.764 | 0 | 1 | Bekleidung | Installationshöhe | 0 | 0 | NEW | 2.5 | AllplanAttributes - ash_lichte Raumhöhe: 2.500000; OKFF: 0; RoomName: Nasszelle DZ
Gipskarton, imprägniert | WUN-H2-E01-041a | CEILING | B 0.1 m | 1166Dfl0000033707/03 | m² | Trockenbauarbeiten | 3 | 0.1 | 0 | 1 | Bekleidung | B | 0 | 0 | NEW | 2.5 | AllplanAttributes - Bezeichnung: Gipskarton, imprägniert; ash_lichte Raumhöhe: 2.500000; OKFF: 0; RoomName: Nasszelle DZ; Pset_CoveringCommon - AcousticRating: -
Gipsfaserplatten 2-lagig (BSK) | WUN-H2-E01-041a | CEILING | D1 0.001 m | 1166Dfl0000033707/04 | m² | Maler- und Lackierarbeiten | 4 | 0.001 | 0 | 1 | Bekleidung | D1 | 0 | 0 | NEW | 2.5 | AllplanAttributes - ash_lichte Raumhöhe: 2.500000; OKFF: 0; RoomName: Nasszelle DZ
a-sh Wandbelag | WUN-H2-E01-041a | CLADDING | 68 0.01 m | 1166Sfl0000664892/01 | m² | Maler- und Lackierarbeiten | 1 | 0.01 | 0 | 1 | Seitenfläche | 68 | 100 | 3000 | NEW | AllplanAttributes - Bezeichnung: a-sh Wandbelag; Attributset-Objekt: Covering
Acrovyn | WUN-H2-E01-090 | CLADDING | 84 0.001 m | 1166Sfl0000220313/02 | m² | Maler- und Lackierarbeiten | 2 | 0.001 | 0 | 1 | Seitenfläche | 84 | 0 | 0 | NEW | AllplanAttributes - Bezeichnung: Acrovyn
Acrovyn | WUN-H2-E01-090 | CLADDING | 84 0.001 m | 1166Sfl0000220317/02 | m² | Maler- und Lackierarbeiten | 2 | 0.001 | 0 | 1 | Seitenfläche | 84 | 0 | 0 | NEW | AllplanAttributes - Bezeichnung: Acrovyn
Gipsfaserplatten 2-lagig (BSK) | WUN-H2-E01-090 | CEILING | layer 0.036 m | 1166Dfl0000034403/01 | m² | Trockenbauarbeiten | 1 | 0.036 | 0 | 1 | Deckenfläche |  | 0 | 0 | NEW | 2.5 | AllplanAttributes - Bezeichnung: Gipsfaserplatten 2-lagig (BSK); RoomName: Doppelzimmer
Gipsfaserplatten 2-lagig (BSK) | WUN-H2-E01-090 | CEILING | Installationshöhe 0.764 m | 1166Dfl0000034403/02 | m² | Trockenbauarbeiten | 2 | 0.764 | 0 | 1 | Bekleidung | Installationshöhe | 0 | 0 | NEW | 2.5 | AllplanAttributes - ash_lichte Raumhöhe: 2.500000; OKFF: 0; RoomName: Doppelzimmer
Gipsfaserplatten 2-lagig (BSK) | WUN-H2-E01-090 | CEILING | A1 0.1 m | 1166Dfl0000034403/03 | m² | Trockenbauarbeiten | 3 | 0.1 | 0 | 1 | Bekleidung | A1 | 0 | 0 | NEW | 2.5 | AllplanAttributes - ash_lichte Raumhöhe: 2.500000; OKFF: 0; RoomName: Doppelzimmer; Pset_CoveringCommon - AcousticRating: -
Gipsfaserplatten 2-lagig (BSK) | WUN-H2-E01-090 | CEILING | D1 0.001 m | 1166Dfl0000034403/04 | m² | Maler- und Lackierarbeiten | 4 | 0.001 | 0 | 1 | Bekleidung | D1 | 0 | 0 | NEW | 2.5 | AllplanAttributes - ash_lichte Raumhöhe: 2.500000; OKFF: 0; RoomName: Doppelzimmer
PVC Bahnenware Holzoptik | WUN-H2-E01-090 | FLOORING | Ku1 0.15 m | 1166Bfl0000034392/01 | m² | Bodenbelagsarbeiten | 1 | 0.15 | 0 | 1 | Bodenfläche | Ku1 | 0 | 0 | NEW | AllplanAttributes - Bezeichnung: PVC Bahnenware Holzoptik; Raumnr. Bauherr: 2.11_A2_02; ash B_Aufbau: B9; ash B_Rutschhemmung: R9
Gipsfaserplatten 2-lagig (BSK) | WUN-H2-E01-090 | CEILING | layer 0.036 m | 1166Dfl0000034393/01 | m² | Trockenbauarbeiten | 1 | 0.036 | 0 | 1 | Deckenfläche |  | 0 | 0 | NEW | 3.15 | AllplanAttributes - Bezeichnung: Gipsfaserplatten 2-lagig (BSK); RoomName: Doppelzimmer
Gipsfaserplatten 2-lagig (BSK) | WUN-H2-E01-090 | CEILING | Installationshöhe 0.114 m | 1166Dfl0000034393/02 | m² | Trockenbauarbeiten | 2 | 0.114 | 0 | 1 | Bekleidung | Installationshöhe | 0 | 0 | NEW | 3.15 | AllplanAttributes - ash_lichte Raumhöhe: 3.150000; RoomName: Doppelzimmer; Pset_CoveringCommon - AcousticRating: -
Gipsfaserplatten 2-lagig (BSK) | WUN-H2-E01-090 | CEILING | A1 0.1 m | 1166Dfl0000034393/03 | m² | Trockenbauarbeiten | 3 | 0.1 | 0 | 1 | Bekleidung | A1 | 0 | 0 | NEW | 3.15 | AllplanAttributes - ash_lichte Raumhöhe: 3.150000; RoomName: Einzelzimmer mit Zustelloption; Pset_CoveringCommon - AcousticRating: -
Gipsfaserplatten 2-lagig (BSK) | WUN-H2-E01-090 | CEILING | D1 0.001 m | 1166Dfl0000034393/04 | m² | Maler- und Lackierarbeiten | 4 | 0.001 | 0 | 1 | Bekleidung | D1 | 0 | 0 | NEW | 3.15 | AllplanAttributes - ash_lichte Raumhöhe: 3.150000; RoomName: Doppelzimmer
 | WUN-H2-E01-090 | CLADDING | 49 0.001 m | 1166Sfl0000665030/01 | m² | Maler- und Lackierarbeiten | 1 | 0.001 | 0 | 1 | Seitenfläche | 49 | 150 | 3150 | NEW
Acrovyn | WUN-H2-E01-091 | CLADDING | 84 0.001 m | 1166Sfl0000220311/02 | m² | Maler- und Lackierarbeiten | 2 | 0.001 | 0 | 1 | Seitenfläche | 84 | 0 | 0 | NEW | AllplanAttributes - Bezeichnung: Acrovyn
Acrovyn | WUN-H2-E01-091 | CLADDING | 84 0.001 m | 1166Sfl0000220315/02 | m² | Maler- und Lackierarbeiten | 2 | 0.001 | 0 | 1 | Seitenfläche | 84 | 0 | 0 | NEW | AllplanAttributes - Bezeichnung: Acrovyn
Gipsfaserplatten 2-lagig (BSK) | WUN-H2-E01-091 | CEILING | layer 0.036 m | 1166Dfl0000034416/01 | m² | Trockenbauarbeiten | 1 | 0.036 | 0 | 1 | Deckenfläche |  | 0 | 0 | NEW | 2.5 | AllplanAttributes - Bezeichnung: Gipsfaserplatten 2-lagig (BSK); RoomName: Doppelzimmer
Gipsfaserplatten 2-lagig (BSK) | WUN-H2-E01-091 | CEILING | Installationshöhe 0.764 m | 1166Dfl0000034416/02 | m² | Trockenbauarbeiten | 2 | 0.764 | 0 | 1 | Bekleidung | Installationshöhe | 0 | 0 | NEW | 2.5 | AllplanAttributes - ash_lichte Raumhöhe: 2.500000; OKFF: 0; RoomName: Doppelzimmer
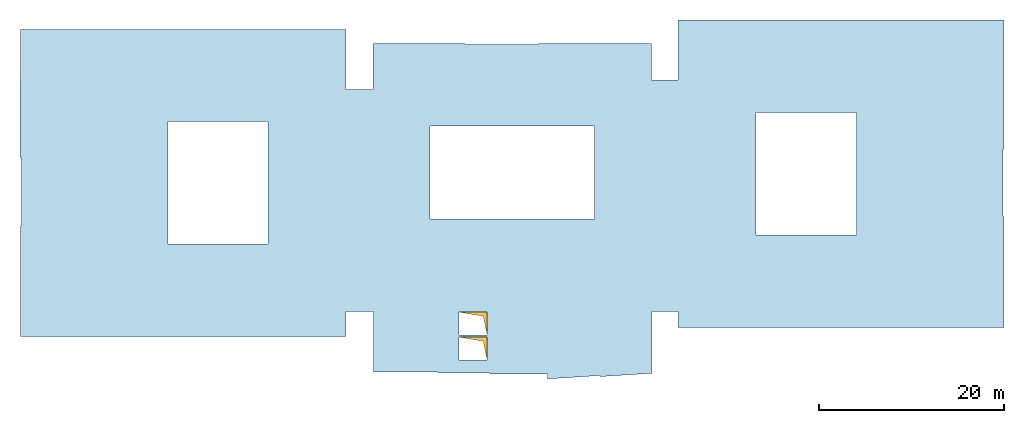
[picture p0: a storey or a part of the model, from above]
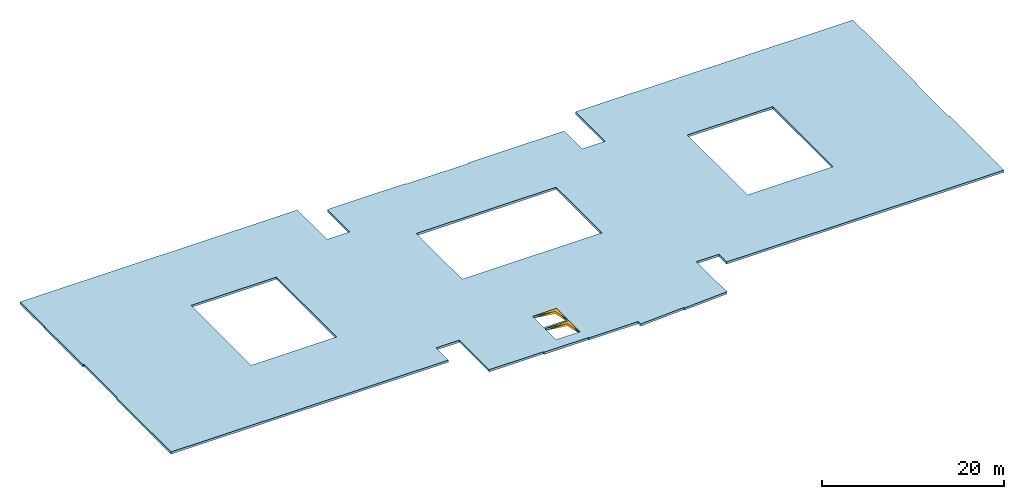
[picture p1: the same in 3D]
Properties of the parts of a building model (IFC4), part 12 of 80

# IfcCovering (3945)
Name | In | PredefinedType | Material | Allright_Bauteil_ID | Abrechnungsart | Gewerk | Schichtnummer | Schichtdicke (m) | Dicke (m) | Faktor | Objektname | AllplanAttributes, Material | Bezugshöhe | Deltahöhe | Status | D_lichte Raumhöhe [Zahl] (m)
Gipsfaserplatten 2-lagig (BSK) | WUN-H2-E01-091 | CEILING | A1 0.1 m | 1166Dfl0000034416/03 | m² | Trockenbauarbeiten | 3 | 0.1 | 0 | 1 | Bekleidung | A1 | 0 | 0 | NEW | 2.5 | AllplanAttributes - ash_lichte Raumhöhe: 2.500000; OKFF: 0; RoomName: Doppelzimmer; Pset_CoveringCommon - AcousticRating: -
Gipsfaserplatten 2-lagig (BSK) | WUN-H2-E01-091 | CEILING | D1 0.001 m | 1166Dfl0000034416/04 | m² | Maler- und Lackierarbeiten | 4 | 0.001 | 0 | 1 | Bekleidung | D1 | 0 | 0 | NEW | 2.5 | AllplanAttributes - ash_lichte Raumhöhe: 2.500000; OKFF: 0; RoomName: Doppelzimmer
PVC Bahnenware Holzoptik | WUN-H2-E01-091 | FLOORING | Ku1 0.15 m | 1166Bfl0000034405/01 | m² | Bodenbelagsarbeiten | 1 | 0.15 | 0 | 1 | Bodenfläche | Ku1 | 0 | 0 | NEW | AllplanAttributes - Bezeichnung: PVC Bahnenware Holzoptik; Raumnr. Bauherr: 2.11_A2_02; ash B_Aufbau: B9; ash B_Rutschhemmung: R9
Gipsfaserplatten 2-lagig (BSK) | WUN-H2-E01-091 | CEILING | layer 0.036 m | 1166Dfl0000034406/01 | m² | Trockenbauarbeiten | 1 | 0.036 | 0 | 1 | Deckenfläche |  | 0 | 0 | NEW | 3.15 | AllplanAttributes - Bezeichnung: Gipsfaserplatten 2-lagig (BSK); RoomName: Doppelzimmer
Gipsfaserplatten 2-lagig (BSK) | WUN-H2-E01-091 | CEILING | Installationshöhe 0.114 m | 1166Dfl0000034406/02 | m² | Trockenbauarbeiten | 2 | 0.114 | 0 | 1 | Bekleidung | Installationshöhe | 0 | 0 | NEW | 3.15 | AllplanAttributes - ash_lichte Raumhöhe: 3.150000; RoomName: Doppelzimmer; Pset_CoveringCommon - AcousticRating: -
Gipsfaserplatten 2-lagig (BSK) | WUN-H2-E01-091 | CEILING | A1 0.1 m | 1166Dfl0000034406/03 | m² | Trockenbauarbeiten | 3 | 0.1 | 0 | 1 | Bekleidung | A1 | 0 | 0 | NEW | 3.15 | AllplanAttributes - ash_lichte Raumhöhe: 3.150000; RoomName: Einzelzimmer mit Zustelloption; Pset_CoveringCommon - AcousticRating: -
Gipsfaserplatten 2-lagig (BSK) | WUN-H2-E01-091 | CEILING | D1 0.001 m | 1166Dfl0000034406/04 | m² | Maler- und Lackierarbeiten | 4 | 0.001 | 0 | 1 | Bekleidung | D1 | 0 | 0 | NEW | 3.15 | AllplanAttributes - ash_lichte Raumhöhe: 3.150000; RoomName: Doppelzimmer
 | WUN-H2-E01-091 | CLADDING | 49 0.001 m | 1166Sfl0000665031/01 | m² | Maler- und Lackierarbeiten | 1 | 0.001 | 0 | 1 | Seitenfläche | 49 | 150 | 3150 | NEW
Acrovyn | WUN-H2-E01-092 | CLADDING | 84 0.001 m | 1166Sfl0000220309/02 | m² | Maler- und Lackierarbeiten | 2 | 0.001 | 0 | 1 | Seitenfläche | 84 | 0 | 0 | NEW | AllplanAttributes - Bezeichnung: Acrovyn
Acrovyn | WUN-H2-E01-092 | CLADDING | 84 0.001 m | 1166Sfl0000220319/02 | m² | Maler- und Lackierarbeiten | 2 | 0.001 | 0 | 1 | Seitenfläche | 84 | 0 | 0 | NEW | AllplanAttributes - Bezeichnung: Acrovyn
Gipsfaserplatten 2-lagig (BSK) | WUN-H2-E01-092 | CEILING | layer 0.036 m | 1166Dfl0000034429/01 | m² | Trockenbauarbeiten | 1 | 0.036 | 0 | 1 | Deckenfläche |  | 0 | 0 | NEW | 2.5 | AllplanAttributes - Bezeichnung: Gipsfaserplatten 2-lagig (BSK); RoomName: Rollstuhlgerechtes Doppelzimmer
Gipsfaserplatten 2-lagig (BSK) | WUN-H2-E01-092 | CEILING | Installationshöhe 0.764 m | 1166Dfl0000034429/02 | m² | Trockenbauarbeiten | 2 | 0.764 | 0 | 1 | Bekleidung | Installationshöhe | 0 | 0 | NEW | 2.5 | AllplanAttributes - ash_lichte Raumhöhe: 2.500000; OKFF: 0; RoomName: Rollstuhlgerechtes Doppelzimmer
Gipsfaserplatten 2-lagig (BSK) | WUN-H2-E01-092 | CEILING | A1 0.1 m | 1166Dfl0000034429/03 | m² | Trockenbauarbeiten | 3 | 0.1 | 0 | 1 | Bekleidung | A1 | 0 | 0 | NEW | 2.5 | AllplanAttributes - ash_lichte Raumhöhe: 2.500000; OKFF: 0; RoomName: Rollstuhlgerechtes Doppelzimmer; Pset_CoveringCommon - AcousticRating: -
Gipsfaserplatten 2-lagig (BSK) | WUN-H2-E01-092 | CEILING | D1 0.001 m | 1166Dfl0000034429/04 | m² | Maler- und Lackierarbeiten | 4 | 0.001 | 0 | 1 | Bekleidung | D1 | 0 | 0 | NEW | 2.5 | AllplanAttributes - ash_lichte Raumhöhe: 2.500000; OKFF: 0; RoomName: Rollstuhlgerechtes Doppelzimmer
PVC Bahnenware Holzoptik | WUN-H2-E01-092 | FLOORING | Ku1 0.15 m | 1166Bfl0000034418/01 | m² | Bodenbelagsarbeiten | 1 | 0.15 | 0 | 1 | Bodenfläche | Ku1 | 0 | 0 | NEW | AllplanAttributes - Bezeichnung: PVC Bahnenware Holzoptik; Raumnr. Bauherr: 2.11_A2_02; ash B_Aufbau: B9; ash B_Rutschhemmung: R9
Gipsfaserplatten 2-lagig (BSK) | WUN-H2-E01-092 | CEILING | layer 0.036 m | 1166Dfl0000034419/01 | m² | Trockenbauarbeiten | 1 | 0.036 | 0 | 1 | Deckenfläche |  | 0 | 0 | NEW | 3.15 | AllplanAttributes - Bezeichnung: Gipsfaserplatten 2-lagig (BSK); RoomName: Rollstuhlgerechtes Doppelzimmer
Gipsfaserplatten 2-lagig (BSK) | WUN-H2-E01-092 | CEILING | Installationshöhe 0.114 m | 1166Dfl0000034419/02 | m² | Trockenbauarbeiten | 2 | 0.114 | 0 | 1 | Bekleidung | Installationshöhe | 0 | 0 | NEW | 3.15 | AllplanAttributes - ash_lichte Raumhöhe: 3.150000; RoomName: Rollstuhlgerechtes Doppelzimmer; Pset_CoveringCommon - AcousticRating: -
Gipsfaserplatten 2-lagig (BSK) | WUN-H2-E01-092 | CEILING | A1 0.1 m | 1166Dfl0000034419/03 | m² | Trockenbauarbeiten | 3 | 0.1 | 0 | 1 | Bekleidung | A1 | 0 | 0 | NEW | 3.15 | AllplanAttributes - ash_lichte Raumhöhe: 3.150000; RoomName: Einzelzimmer mit Zustelloption; Pset_CoveringCommon - AcousticRating: -
Gipsfaserplatten 2-lagig (BSK) | WUN-H2-E01-092 | CEILING | D1 0.001 m | 1166Dfl0000034419/04 | m² | Maler- und Lackierarbeiten | 4 | 0.001 | 0 | 1 | Bekleidung | D1 | 0 | 0 | NEW | 3.15 | AllplanAttributes - ash_lichte Raumhöhe: 3.150000; RoomName: Rollstuhlgerechtes Doppelzimmer
 | WUN-H2-E01-092 | CLADDING | 49 0.001 m | 1166Sfl0000665032/01 | m² | Maler- und Lackierarbeiten | 1 | 0.001 | 0 | 1 | Seitenfläche | 49 | 150 | 3150 | NEW
Acrovyn | WUN-H2-E01-093 | CLADDING | 84 0.001 m | 1166Sfl0000220321/02 | m² | Maler- und Lackierarbeiten | 2 | 0.001 | 0 | 1 | Seitenfläche | 84 | 0 | 0 | NEW | AllplanAttributes - Bezeichnung: Acrovyn
Gipsfaserplatten 2-lagig (BSK) | WUN-H2-E01-093 | CEILING | layer 0.036 m | 1166Dfl0000034442/01 | m² | Trockenbauarbeiten | 1 | 0.036 | 0 | 1 | Deckenfläche |  | 0 | 0 | NEW | 2.5 | AllplanAttributes - Bezeichnung: Gipsfaserplatten 2-lagig (BSK); RoomName: Einzelzimmer
Gipsfaserplatten 2-lagig (BSK) | WUN-H2-E01-093 | CEILING | Installationshöhe 0.764 m | 1166Dfl0000034442/02 | m² | Trockenbauarbeiten | 2 | 0.764 | 0 | 1 | Bekleidung | Installationshöhe | 0 | 0 | NEW | 2.5 | AllplanAttributes - ash_lichte Raumhöhe: 2.500000; OKFF: 0; RoomName: Einzelzimmer
Gipsfaserplatten 2-lagig (BSK) | WUN-H2-E01-093 | CEILING | A1 0.1 m | 1166Dfl0000034442/03 | m² | Trockenbauarbeiten | 3 | 0.1 | 0 | 1 | Bekleidung | A1 | 0 | 0 | NEW | 2.5 | AllplanAttributes - ash_lichte Raumhöhe: 2.500000; OKFF: 0; RoomName: Einzelzimmer; Pset_CoveringCommon - AcousticRating: -
Gipsfaserplatten 2-lagig (BSK) | WUN-H2-E01-093 | CEILING | D1 0.001 m | 1166Dfl0000034442/04 | m² | Maler- und Lackierarbeiten | 4 | 0.001 | 0 | 1 | Bekleidung | D1 | 0 | 0 | NEW | 2.5 | AllplanAttributes - ash_lichte Raumhöhe: 2.500000; OKFF: 0; RoomName: Einzelzimmer
PVC Bahnenware Holzoptik | WUN-H2-E01-093 | FLOORING | Ku1 0.15 m | 1166Bfl0000034431/01 | m² | Bodenbelagsarbeiten | 1 | 0.15 | 0 | 1 | Bodenfläche | Ku1 | 0 | 0 | NEW | AllplanAttributes - Bezeichnung: PVC Bahnenware Holzoptik; Raumnr. Bauherr: 2.11_A2_02; ash B_Aufbau: B9; ash B_Rutschhemmung: R9
Gipsfaserplatten 2-lagig (BSK) | WUN-H2-E01-093 | CEILING | layer 0.036 m | 1166Dfl0000034432/01 | m² | Trockenbauarbeiten | 1 | 0.036 | 0 | 1 | Deckenfläche |  | 0 | 0 | NEW | 3.15 | AllplanAttributes - Bezeichnung: Gipsfaserplatten 2-lagig (BSK); RoomName: Einzelzimmer
Gipsfaserplatten 2-lagig (BSK) | WUN-H2-E01-093 | CEILING | Installationshöhe 0.114 m | 1166Dfl0000034432/02 | m² | Trockenbauarbeiten | 2 | 0.114 | 0 | 1 | Bekleidung | Installationshöhe | 0 | 0 | NEW | 3.15 | AllplanAttributes - ash_lichte Raumhöhe: 3.150000; RoomName: Einzelzimmer; Pset_CoveringCommon - AcousticRating: -
Gipsfaserplatten 2-lagig (BSK) | WUN-H2-E01-093 | CEILING | A1 0.1 m | 1166Dfl0000034432/03 | m² | Trockenbauarbeiten | 3 | 0.1 | 0 | 1 | Bekleidung | A1 | 0 | 0 | NEW | 3.15 | AllplanAttributes - ash_lichte Raumhöhe: 3.150000; RoomName: Einzelzimmer mit Zustelloption; Pset_CoveringCommon - AcousticRating: -
Gipsfaserplatten 2-lagig (BSK) | WUN-H2-E01-093 | CEILING | D1 0.001 m | 1166Dfl0000034432/04 | m² | Maler- und Lackierarbeiten | 4 | 0.001 | 0 | 1 | Bekleidung | D1 | 0 | 0 | NEW | 3.15 | AllplanAttributes - ash_lichte Raumhöhe: 3.150000; RoomName: Einzelzimmer
 | WUN-H2-E01-093 | CLADDING | 49 0.001 m | 1166Sfl0000665033/01 | m² | Maler- und Lackierarbeiten | 1 | 0.001 | 0 | 1 | Seitenfläche | 49 | 150 | 3150 | NEW
Acrovyn | WUN-H2-E01-094 | CLADDING | 84 0.001 m | 1166Sfl0000220307/02 | m² | Maler- und Lackierarbeiten | 2 | 0.001 | 0 | 1 | Seitenfläche | 84 | 0 | 0 | NEW | AllplanAttributes - Bezeichnung: Acrovyn
Acrovyn | WUN-H2-E01-094 | CLADDING | 84 0.001 m | 1166Sfl0000220323/02 | m² | Maler- und Lackierarbeiten | 2 | 0.001 | 0 | 1 | Seitenfläche | 84 | 0 | 0 | NEW | AllplanAttributes - Bezeichnung: Acrovyn
Gipsfaserplatten 2-lagig (BSK) | WUN-H2-E01-094 | CEILING | layer 0.036 m | 1166Dfl0000034499/01 | m² | Trockenbauarbeiten | 1 | 0.036 | 0 | 1 | Deckenfläche |  | 0 | 0 | NEW | 2.5 | AllplanAttributes - Bezeichnung: Gipsfaserplatten 2-lagig (BSK); RoomName: Doppelzimmer
Gipsfaserplatten 2-lagig (BSK) | WUN-H2-E01-094 | CEILING | Installationshöhe 0.764 m | 1166Dfl0000034499/02 | m² | Trockenbauarbeiten | 2 | 0.764 | 0 | 1 | Bekleidung | Installationshöhe | 0 | 0 | NEW | 2.5 | AllplanAttributes - ash_lichte Raumhöhe: 2.500000; OKFF: 0; RoomName: Doppelzimmer
Gipsfaserplatten 2-lagig (BSK) | WUN-H2-E01-094 | CEILING | A1 0.1 m | 1166Dfl0000034499/03 | m² | Trockenbauarbeiten | 3 | 0.1 | 0 | 1 | Bekleidung | A1 | 0 | 0 | NEW | 2.5 | AllplanAttributes - ash_lichte Raumhöhe: 2.500000; OKFF: 0; RoomName: Doppelzimmer; Pset_CoveringCommon - AcousticRating: -
Gipsfaserplatten 2-lagig (BSK) | WUN-H2-E01-094 | CEILING | D1 0.001 m | 1166Dfl0000034499/04 | m² | Maler- und Lackierarbeiten | 4 | 0.001 | 0 | 1 | Bekleidung | D1 | 0 | 0 | NEW | 2.5 | AllplanAttributes - ash_lichte Raumhöhe: 2.500000; OKFF: 0; RoomName: Doppelzimmer
PVC Bahnenware Holzoptik | WUN-H2-E01-094 | FLOORING | Ku1 0.15 m | 1166Bfl0000034488/01 | m² | Bodenbelagsarbeiten | 1 | 0.15 | 0 | 1 | Bodenfläche | Ku1 | 0 | 0 | NEW | AllplanAttributes - Bezeichnung: PVC Bahnenware Holzoptik; Raumnr. Bauherr: 2.11_A2_02; ash B_Aufbau: B9; ash B_Rutschhemmung: R9
Gipsfaserplatten 2-lagig (BSK) | WUN-H2-E01-094 | CEILING | layer 0.036 m | 1166Dfl0000034489/01 | m² | Trockenbauarbeiten | 1 | 0.036 | 0 | 1 | Deckenfläche |  | 0 | 0 | NEW | 3.15 | AllplanAttributes - Bezeichnung: Gipsfaserplatten 2-lagig (BSK); RoomName: Doppelzimmer
Gipsfaserplatten 2-lagig (BSK) | WUN-H2-E01-094 | CEILING | Installationshöhe 0.114 m | 1166Dfl0000034489/02 | m² | Trockenbauarbeiten | 2 | 0.114 | 0 | 1 | Bekleidung | Installationshöhe | 0 | 0 | NEW | 3.15 | AllplanAttributes - ash_lichte Raumhöhe: 3.150000; RoomName: Doppelzimmer; Pset_CoveringCommon - AcousticRating: -
Gipsfaserplatten 2-lagig (BSK) | WUN-H2-E01-094 | CEILING | A1 0.1 m | 1166Dfl0000034489/03 | m² | Trockenbauarbeiten | 3 | 0.1 | 0 | 1 | Bekleidung | A1 | 0 | 0 | NEW | 3.15 | AllplanAttributes - ash_lichte Raumhöhe: 3.150000; RoomName: Einzelzimmer mit Zustelloption; Pset_CoveringCommon - AcousticRating: -
Gipsfaserplatten 2-lagig (BSK) | WUN-H2-E01-094 | CEILING | D1 0.001 m | 1166Dfl0000034489/04 | m² | Maler- und Lackierarbeiten | 4 | 0.001 | 0 | 1 | Bekleidung | D1 | 0 | 0 | NEW | 3.15 | AllplanAttributes - ash_lichte Raumhöhe: 3.150000; RoomName: Doppelzimmer
 | WUN-H2-E01-094 | CLADDING | 49 0.001 m | 1166Sfl0000665034/01 | m² | Maler- und Lackierarbeiten | 1 | 0.001 | 0 | 1 | Seitenfläche | 49 | 150 | 3150 | NEW
Acrovyn | WUN-H2-E01-095 | CLADDING | 84 0.001 m | 1166Sfl0000220305/02 | m² | Maler- und Lackierarbeiten | 2 | 0.001 | 0 | 1 | Seitenfläche | 84 | 0 | 0 | NEW | AllplanAttributes - Bezeichnung: Acrovyn
Acrovyn | WUN-H2-E01-095 | CLADDING | 84 0.001 m | 1166Sfl0000220325/02 | m² | Maler- und Lackierarbeiten | 2 | 0.001 | 0 | 1 | Seitenfläche | 84 | 0 | 0 | NEW | AllplanAttributes - Bezeichnung: Acrovyn
Gipsfaserplatten 2-lagig (BSK) | WUN-H2-E01-095 | CEILING | layer 0.036 m | 1166Dfl0000034523/01 | m² | Trockenbauarbeiten | 1 | 0.036 | 0 | 1 | Deckenfläche |  | 0 | 0 | NEW | 2.5 | AllplanAttributes - Bezeichnung: Gipsfaserplatten 2-lagig (BSK); RoomName: Doppelzimmer
Gipsfaserplatten 2-lagig (BSK) | WUN-H2-E01-095 | CEILING | Installationshöhe 0.764 m | 1166Dfl0000034523/02 | m² | Trockenbauarbeiten | 2 | 0.764 | 0 | 1 | Bekleidung | Installationshöhe | 0 | 0 | NEW | 2.5 | AllplanAttributes - ash_lichte Raumhöhe: 2.500000; OKFF: 0; RoomName: Doppelzimmer
Gipsfaserplatten 2-lagig (BSK) | WUN-H2-E01-095 | CEILING | A1 0.1 m | 1166Dfl0000034523/03 | m² | Trockenbauarbeiten | 3 | 0.1 | 0 | 1 | Bekleidung | A1 | 0 | 0 | NEW | 2.5 | AllplanAttributes - ash_lichte Raumhöhe: 2.500000; OKFF: 0; RoomName: Doppelzimmer; Pset_CoveringCommon - AcousticRating: -
Gipsfaserplatten 2-lagig (BSK) | WUN-H2-E01-095 | CEILING | D1 0.001 m | 1166Dfl0000034523/04 | m² | Maler- und Lackierarbeiten | 4 | 0.001 | 0 | 1 | Bekleidung | D1 | 0 | 0 | NEW | 2.5 | AllplanAttributes - ash_lichte Raumhöhe: 2.500000; OKFF: 0; RoomName: Doppelzimmer
PVC Bahnenware Holzoptik | WUN-H2-E01-095 | FLOORING | Ku1 0.15 m | 1166Bfl0000034512/01 | m² | Bodenbelagsarbeiten | 1 | 0.15 | 0 | 1 | Bodenfläche | Ku1 | 0 | 0 | NEW | AllplanAttributes - Bezeichnung: PVC Bahnenware Holzoptik; Raumnr. Bauherr: 2.11_A2_02; ash B_Aufbau: B9; ash B_Rutschhemmung: R9
Gipsfaserplatten 2-lagig (BSK) | WUN-H2-E01-095 | CEILING | layer 0.036 m | 1166Dfl0000034513/01 | m² | Trockenbauarbeiten | 1 | 0.036 | 0 | 1 | Deckenfläche |  | 0 | 0 | NEW | 3.15 | AllplanAttributes - Bezeichnung: Gipsfaserplatten 2-lagig (BSK); RoomName: Doppelzimmer
Gipsfaserplatten 2-lagig (BSK) | WUN-H2-E01-095 | CEILING | Installationshöhe 0.114 m | 1166Dfl0000034513/02 | m² | Trockenbauarbeiten | 2 | 0.114 | 0 | 1 | Bekleidung | Installationshöhe | 0 | 0 | NEW | 3.15 | AllplanAttributes - ash_lichte Raumhöhe: 3.150000; RoomName: Doppelzimmer; Pset_CoveringCommon - AcousticRating: -
Gipsfaserplatten 2-lagig (BSK) | WUN-H2-E01-095 | CEILING | A1 0.1 m | 1166Dfl0000034513/03 | m² | Trockenbauarbeiten | 3 | 0.1 | 0 | 1 | Bekleidung | A1 | 0 | 0 | NEW | 3.15 | AllplanAttributes - ash_lichte Raumhöhe: 3.150000; RoomName: Einzelzimmer mit Zustelloption; Pset_CoveringCommon - AcousticRating: -
Gipsfaserplatten 2-lagig (BSK) | WUN-H2-E01-095 | CEILING | D1 0.001 m | 1166Dfl0000034513/04 | m² | Maler- und Lackierarbeiten | 4 | 0.001 | 0 | 1 | Bekleidung | D1 | 0 | 0 | NEW | 3.15 | AllplanAttributes - ash_lichte Raumhöhe: 3.150000; RoomName: Doppelzimmer
 | WUN-H2-E01-095 | CLADDING | 49 0.001 m | 1166Sfl0000665035/01 | m² | Maler- und Lackierarbeiten | 1 | 0.001 | 0 | 1 | Seitenfläche | 49 | 150 | 3150 | NEW
Acrovyn | WUN-H2-E01-096 | CLADDING | 84 0.001 m | 1166Sfl0000220303/02 | m² | Maler- und Lackierarbeiten | 2 | 0.001 | 0 | 1 | Seitenfläche | 84 | 0 | 0 | NEW | AllplanAttributes - Bezeichnung: Acrovyn
Acrovyn | WUN-H2-E01-096 | CLADDING | 84 0.001 m | 1166Sfl0000220327/02 | m² | Maler- und Lackierarbeiten | 2 | 0.001 | 0 | 1 | Seitenfläche | 84 | 0 | 0 | NEW | AllplanAttributes - Bezeichnung: Acrovyn
Gipsfaserplatten 2-lagig (BSK) | WUN-H2-E01-096 | CEILING | layer 0.036 m | 1166Dfl0000034547/01 | m² | Trockenbauarbeiten | 1 | 0.036 | 0 | 1 | Deckenfläche |  | 0 | 0 | NEW | 2.5 | AllplanAttributes - Bezeichnung: Gipsfaserplatten 2-lagig (BSK); RoomName: Einzelzimmer mit Zustelloption
Gipsfaserplatten 2-lagig (BSK) | WUN-H2-E01-096 | CEILING | Installationshöhe 0.764 m | 1166Dfl0000034547/02 | m² | Trockenbauarbeiten | 2 | 0.764 | 0 | 1 | Bekleidung | Installationshöhe | 0 | 0 | NEW | 2.5 | AllplanAttributes - ash_lichte Raumhöhe: 2.500000; OKFF: 0; RoomName: Einzelzimmer mit Zustelloption
Gipsfaserplatten 2-lagig (BSK) | WUN-H2-E01-096 | CEILING | A1 0.1 m | 1166Dfl0000034547/03 | m² | Trockenbauarbeiten | 3 | 0.1 | 0 | 1 | Bekleidung | A1 | 0 | 0 | NEW | 2.5 | AllplanAttributes - ash_lichte Raumhöhe: 2.500000; OKFF: 0; RoomName: Einzelzimmer mit Zustelloption; Pset_CoveringCommon - AcousticRating: -
Gipsfaserplatten 2-lagig (BSK) | WUN-H2-E01-096 | CEILING | D1 0.001 m | 1166Dfl0000034547/04 | m² | Maler- und Lackierarbeiten | 4 | 0.001 | 0 | 1 | Bekleidung | D1 | 0 | 0 | NEW | 2.5 | AllplanAttributes - ash_lichte Raumhöhe: 2.500000; OKFF: 0; RoomName: Einzelzimmer mit Zustelloption
PVC Bahnenware Holzoptik | WUN-H2-E01-096 | FLOORING | Ku1 0.15 m | 1166Bfl0000034536/01 | m² | Bodenbelagsarbeiten | 1 | 0.15 | 0 | 1 | Bodenfläche | Ku1 | 0 | 0 | NEW | AllplanAttributes - Bezeichnung: PVC Bahnenware Holzoptik; Raumnr. Bauherr: 2.11_A2_02; ash B_Aufbau: B9; ash B_Rutschhemmung: R9
Gipsfaserplatten 2-lagig (BSK) | WUN-H2-E01-096 | CEILING | layer 0.036 m | 1166Dfl0000034537/01 | m² | Trockenbauarbeiten | 1 | 0.036 | 0 | 1 | Deckenfläche |  | 0 | 0 | NEW | 3.15 | AllplanAttributes - Bezeichnung: Gipsfaserplatten 2-lagig (BSK); RoomName: Einzelzimmer mit Zustelloption
Gipsfaserplatten 2-lagig (BSK) | WUN-H2-E01-096 | CEILING | Installationshöhe 0.114 m | 1166Dfl0000034537/02 | m² | Trockenbauarbeiten | 2 | 0.114 | 0 | 1 | Bekleidung | Installationshöhe | 0 | 0 | NEW | 3.15 | AllplanAttributes - ash_lichte Raumhöhe: 3.150000; RoomName: Einzelzimmer mit Zustelloption; Pset_CoveringCommon - AcousticRating: -
Gipsfaserplatten 2-lagig (BSK) | WUN-H2-E01-096 | CEILING | A1 0.1 m | 1166Dfl0000034537/03 | m² | Trockenbauarbeiten | 3 | 0.1 | 0 | 1 | Bekleidung | A1 | 0 | 0 | NEW | 3.15 | AllplanAttributes - ash_lichte Raumhöhe: 3.150000; RoomName: Einzelzimmer mit Zustelloption; Pset_CoveringCommon - AcousticRating: -
Gipsfaserplatten 2-lagig (BSK) | WUN-H2-E01-096 | CEILING | D1 0.001 m | 1166Dfl0000034537/04 | m² | Maler- und Lackierarbeiten | 4 | 0.001 | 0 | 1 | Bekleidung | D1 | 0 | 0 | NEW | 3.15 | AllplanAttributes - ash_lichte Raumhöhe: 3.150000; RoomName: Einzelzimmer mit Zustelloption
 | WUN-H2-E01-096 | CLADDING | 49 0.001 m | 1166Sfl0000665036/01 | m² | Maler- und Lackierarbeiten | 1 | 0.001 | 0 | 1 | Seitenfläche | 49 | 150 | 3150 | NEW
Acrovyn | WUN-H2-E01-019 | CLADDING | 84 0.001 m | 1166Sfl0000220301/02 | m² | Maler- und Lackierarbeiten | 2 | 0.001 | 0 | 1 | Seitenfläche | 84 | 0 | 0 | NEW | AllplanAttributes - Bezeichnung: Acrovyn
Acrovyn | WUN-H2-E01-019 | CLADDING | 84 0.001 m | 1166Sfl0000220339/02 | m² | Maler- und Lackierarbeiten | 2 | 0.001 | 0 | 1 | Seitenfläche | 84 | 0 | 0 | NEW | AllplanAttributes - Bezeichnung: Acrovyn
Gipsfaserplatten 2-lagig (BSK) | WUN-H2-E01-019 | CEILING | layer 0.036 m | 1166Dfl0000033296/01 | m² | Trockenbauarbeiten | 1 | 0.036 | 0 | 1 | Deckenfläche |  | 0 | 0 | NEW | 2.5 | AllplanAttributes - Bezeichnung: Gipsfaserplatten 2-lagig (BSK); RoomName: Einzelzimmer mit Zustelloption
Gipsfaserplatten 2-lagig (BSK) | WUN-H2-E01-019 | CEILING | Installationshöhe 0.764 m | 1166Dfl0000033296/02 | m² | Trockenbauarbeiten | 2 | 0.764 | 0 | 1 | Bekleidung | Installationshöhe | 0 | 0 | NEW | 2.5 | AllplanAttributes - ash_lichte Raumhöhe: 2.500000; OKFF: 0; RoomName: Einzelzimmer mit Zustelloption
Gipsfaserplatten 2-lagig (BSK) | WUN-H2-E01-019 | CEILING | A1 0.1 m | 1166Dfl0000033296/03 | m² | Trockenbauarbeiten | 3 | 0.1 | 0 | 1 | Bekleidung | A1 | 0 | 0 | NEW | 2.5 | AllplanAttributes - ash_lichte Raumhöhe: 2.500000; OKFF: 0; RoomName: Einzelzimmer mit Zustelloption; Pset_CoveringCommon - AcousticRating: -
Gipsfaserplatten 2-lagig (BSK) | WUN-H2-E01-019 | CEILING | D1 0.001 m | 1166Dfl0000033296/04 | m² | Maler- und Lackierarbeiten | 4 | 0.001 | 0 | 1 | Bekleidung | D1 | 0 | 0 | NEW | 2.5 | AllplanAttributes - ash_lichte Raumhöhe: 2.500000; OKFF: 0; RoomName: Einzelzimmer mit Zustelloption
PVC Bahnenware Holzoptik | WUN-H2-E01-019 | FLOORING | Ku1 0.15 m | 1166Bfl0000033286/01 | m² | Bodenbelagsarbeiten | 1 | 0.15 | 0 | 1 | Bodenfläche | Ku1 | 0 | 0 | NEW | AllplanAttributes - Bezeichnung: PVC Bahnenware Holzoptik; Raumnr. Bauherr: 2.11_A2_02; ash B_Aufbau: B9; ash B_Rutschhemmung: R9
Gipsfaserplatten 2-lagig (BSK) | WUN-H2-E01-019 | CEILING | layer 0.036 m | 1166Dfl0000033285/01 | m² | Trockenbauarbeiten | 1 | 0.036 | 0 | 1 | Deckenfläche |  | 0 | 0 | NEW | 3.15 | AllplanAttributes - Bezeichnung: Gipsfaserplatten 2-lagig (BSK); RoomName: Einzelzimmer mit Zustelloption
Gipsfaserplatten 2-lagig (BSK) | WUN-H2-E01-019 | CEILING | Installationshöhe 0.114 m | 1166Dfl0000033285/02 | m² | Trockenbauarbeiten | 2 | 0.114 | 0 | 1 | Bekleidung | Installationshöhe | 0 | 0 | NEW | 3.15 | AllplanAttributes - ash_lichte Raumhöhe: 3.150000; RoomName: Einzelzimmer mit Zustelloption; Pset_CoveringCommon - AcousticRating: -
Gipsfaserplatten 2-lagig (BSK) | WUN-H2-E01-019 | CEILING | A1 0.1 m | 1166Dfl0000033285/03 | m² | Trockenbauarbeiten | 3 | 0.1 | 0 | 1 | Bekleidung | A1 | 0 | 0 | NEW | 3.15 | AllplanAttributes - ash_lichte Raumhöhe: 3.150000; RoomName: Doppelzimmer; Pset_CoveringCommon - AcousticRating: -
Gipsfaserplatten 2-lagig (BSK) | WUN-H2-E01-019 | CEILING | D1 0.001 m | 1166Dfl0000033285/04 | m² | Maler- und Lackierarbeiten | 4 | 0.001 | 0 | 1 | Bekleidung | D1 | 0 | 0 | NEW | 3.15 | AllplanAttributes - ash_lichte Raumhöhe: 3.150000; RoomName: Einzelzimmer mit Zustelloption
 | WUN-H2-E01-019 | CLADDING | 49 0.001 m | 1166Sfl0000665037/01 | m² | Maler- und Lackierarbeiten | 1 | 0.001 | 0 | 1 | Seitenfläche | 49 | 150 | 3150 | NEW
Acrovyn | WUN-H2-E01-020 | CLADDING | 84 0.001 m | 1166Sfl0000220299/02 | m² | Maler- und Lackierarbeiten | 2 | 0.001 | 0 | 1 | Seitenfläche | 84 | 0 | 0 | NEW | AllplanAttributes - Bezeichnung: Acrovyn
Acrovyn | WUN-H2-E01-020 | CLADDING | 84 0.001 m | 1166Sfl0000220329/02 | m² | Maler- und Lackierarbeiten | 2 | 0.001 | 0 | 1 | Seitenfläche | 84 | 0 | 0 | NEW | AllplanAttributes - Bezeichnung: Acrovyn
Gipsfaserplatten 2-lagig (BSK) | WUN-H2-E01-020 | CEILING | layer 0.036 m | 1166Dfl0000033309/01 | m² | Trockenbauarbeiten | 1 | 0.036 | 0 | 1 | Deckenfläche |  | 0 | 0 | NEW | 2.5 | AllplanAttributes - Bezeichnung: Gipsfaserplatten 2-lagig (BSK); RoomName: Doppelzimmer
Gipsfaserplatten 2-lagig (BSK) | WUN-H2-E01-020 | CEILING | Installationshöhe 0.764 m | 1166Dfl0000033309/02 | m² | Trockenbauarbeiten | 2 | 0.764 | 0 | 1 | Bekleidung | Installationshöhe | 0 | 0 | NEW | 2.5 | AllplanAttributes - ash_lichte Raumhöhe: 2.500000; OKFF: 0; RoomName: Doppelzimmer
Gipsfaserplatten 2-lagig (BSK) | WUN-H2-E01-020 | CEILING | A1 0.1 m | 1166Dfl0000033309/03 | m² | Trockenbauarbeiten | 3 | 0.1 | 0 | 1 | Bekleidung | A1 | 0 | 0 | NEW | 2.5 | AllplanAttributes - ash_lichte Raumhöhe: 2.500000; OKFF: 0; RoomName: Doppelzimmer; Pset_CoveringCommon - AcousticRating: -
Gipsfaserplatten 2-lagig (BSK) | WUN-H2-E01-020 | CEILING | D1 0.001 m | 1166Dfl0000033309/04 | m² | Maler- und Lackierarbeiten | 4 | 0.001 | 0 | 1 | Bekleidung | D1 | 0 | 0 | NEW | 2.5 | AllplanAttributes - ash_lichte Raumhöhe: 2.500000; OKFF: 0; RoomName: Doppelzimmer
PVC Bahnenware Holzoptik | WUN-H2-E01-020 | FLOORING | Ku1 0.15 m | 1166Bfl0000033298/01 | m² | Bodenbelagsarbeiten | 1 | 0.15 | 0 | 1 | Bodenfläche | Ku1 | 0 | 0 | NEW | AllplanAttributes - Bezeichnung: PVC Bahnenware Holzoptik; Raumnr. Bauherr: 2.11_A2_02; ash B_Aufbau: B9; ash B_Rutschhemmung: R9
Gipsfaserplatten 2-lagig (BSK) | WUN-H2-E01-020 | CEILING | layer 0.036 m | 1166Dfl0000033299/01 | m² | Trockenbauarbeiten | 1 | 0.036 | 0 | 1 | Deckenfläche |  | 0 | 0 | NEW | 3.15 | AllplanAttributes - Bezeichnung: Gipsfaserplatten 2-lagig (BSK); RoomName: Doppelzimmer
Gipsfaserplatten 2-lagig (BSK) | WUN-H2-E01-020 | CEILING | Installationshöhe 0.114 m | 1166Dfl0000033299/02 | m² | Trockenbauarbeiten | 2 | 0.114 | 0 | 1 | Bekleidung | Installationshöhe | 0 | 0 | NEW | 3.15 | AllplanAttributes - ash_lichte Raumhöhe: 3.150000; RoomName: Doppelzimmer; Pset_CoveringCommon - AcousticRating: -
Gipsfaserplatten 2-lagig (BSK) | WUN-H2-E01-020 | CEILING | A1 0.1 m | 1166Dfl0000033299/03 | m² | Trockenbauarbeiten | 3 | 0.1 | 0 | 1 | Bekleidung | A1 | 0 | 0 | NEW | 3.15 | AllplanAttributes - ash_lichte Raumhöhe: 3.150000; RoomName: Doppelzimmer; Pset_CoveringCommon - AcousticRating: -
Gipsfaserplatten 2-lagig (BSK) | WUN-H2-E01-020 | CEILING | D1 0.001 m | 1166Dfl0000033299/04 | m² | Maler- und Lackierarbeiten | 4 | 0.001 | 0 | 1 | Bekleidung | D1 | 0 | 0 | NEW | 3.15 | AllplanAttributes - ash_lichte Raumhöhe: 3.150000; RoomName: Doppelzimmer
 | WUN-H2-E01-020 | CLADDING | 49 0.001 m | 1166Sfl0000665038/01 | m² | Maler- und Lackierarbeiten | 1 | 0.001 | 0 | 1 | Seitenfläche | 49 | 150 | 3150 | NEW
Acrovyn | WUN-H2-E01-047 | CLADDING | 84 0.001 m | 1166Sfl0000220398/02 | m² | Maler- und Lackierarbeiten | 2 | 0.001 | 0 | 1 | Seitenfläche | 84 | 0 | 0 | NEW | AllplanAttributes - Bezeichnung: Acrovyn
Gipsfaserplatten 2-lagig (BSK) | WUN-H2-E01-047 | CEILING | layer 0.036 m | 1166Dfl0000033627/01 | m² | Trockenbauarbeiten | 1 | 0.036 | 0 | 1 | Deckenfläche |  | 0 | 0 | NEW | 2.5 | AllplanAttributes - Bezeichnung: Gipsfaserplatten 2-lagig (BSK); RoomName: Einzelzimmer Adipositas
Gipsfaserplatten 2-lagig (BSK) | WUN-H2-E01-047 | CEILING | Installationshöhe 0.764 m | 1166Dfl0000033627/02 | m² | Trockenbauarbeiten | 2 | 0.764 | 0 | 1 | Bekleidung | Installationshöhe | 0 | 0 | NEW | 2.5 | AllplanAttributes - ash_lichte Raumhöhe: 2.500000; OKFF: 0; RoomName: Einzelzimmer Adipositas
Gipsfaserplatten 2-lagig (BSK) | WUN-H2-E01-047 | CEILING | A1 0.1 m | 1166Dfl0000033627/03 | m² | Trockenbauarbeiten | 3 | 0.1 | 0 | 1 | Bekleidung | A1 | 0 | 0 | NEW | 2.5 | AllplanAttributes - ash_lichte Raumhöhe: 2.500000; OKFF: 0; RoomName: Einzelzimmer Adipositas; Pset_CoveringCommon - AcousticRating: -
Gipsfaserplatten 2-lagig (BSK) | WUN-H2-E01-047 | CEILING | D1 0.001 m | 1166Dfl0000033627/04 | m² | Maler- und Lackierarbeiten | 4 | 0.001 | 0 | 1 | Bekleidung | D1 | 0 | 0 | NEW | 2.5 | AllplanAttributes - ash_lichte Raumhöhe: 2.500000; OKFF: 0; RoomName: Einzelzimmer Adipositas
PVC Bahnenware Holzoptik | WUN-H2-E01-047 | FLOORING | Ku1 0.15 m | 1166Bfl0000033617/01 | m² | Bodenbelagsarbeiten | 1 | 0.15 | 0 | 1 | Bodenfläche | Ku1 | 0 | 0 | NEW | AllplanAttributes - Bezeichnung: PVC Bahnenware Holzoptik; Raumnr. Bauherr: 2.11_A2_02; ash B_Aufbau: B9; ash B_Rutschhemmung: R9
Gipsfaserplatten 2-lagig (BSK) | WUN-H2-E01-047 | CEILING | layer 0.036 m | 1166Dfl0000033616/01 | m² | Trockenbauarbeiten | 1 | 0.036 | 0 | 1 | Deckenfläche |  | 0 | 0 | NEW | 3.15 | AllplanAttributes - Bezeichnung: Gipsfaserplatten 2-lagig (BSK); RoomName: Doppelzimmer
Gipsfaserplatten 2-lagig (BSK) | WUN-H2-E01-047 | CEILING | Installationshöhe 0.114 m | 1166Dfl0000033616/02 | m² | Trockenbauarbeiten | 2 | 0.114 | 0 | 1 | Bekleidung | Installationshöhe | 0 | 0 | NEW | 3.15 | AllplanAttributes - ash_lichte Raumhöhe: 3.150000; RoomName: Doppelzimmer; Pset_CoveringCommon - AcousticRating: -
Gipsfaserplatten 2-lagig (BSK) | WUN-H2-E01-047 | CEILING | A1 0.1 m | 1166Dfl0000033616/03 | m² | Trockenbauarbeiten | 3 | 0.1 | 0 | 1 | Bekleidung | A1 | 0 | 0 | NEW | 3.15 | AllplanAttributes - ash_lichte Raumhöhe: 3.150000; RoomName: Doppelzimmer; Pset_CoveringCommon - AcousticRating: -
Gipsfaserplatten 2-lagig (BSK) | WUN-H2-E01-047 | CEILING | D1 0.001 m | 1166Dfl0000033616/04 | m² | Maler- und Lackierarbeiten | 4 | 0.001 | 0 | 1 | Bekleidung | D1 | 0 | 0 | NEW | 3.15 | AllplanAttributes - ash_lichte Raumhöhe: 3.150000; RoomName: Doppelzimmer
 | WUN-H2-E01-047 | CLADDING | 49 0.001 m | 1166Sfl0000665039/01 | m² | Maler- und Lackierarbeiten | 1 | 0.001 | 0 | 1 | Seitenfläche | 49 | 150 | 3150 | NEW
Acrovyn | WUN-H2-E01-046 | CLADDING | 84 0.001 m | 1166Sfl0000220364/02 | m² | Maler- und Lackierarbeiten | 2 | 0.001 | 0 | 1 | Seitenfläche | 84 | 0 | 0 | NEW | AllplanAttributes - Bezeichnung: Acrovyn
Acrovyn | WUN-H2-E01-046 | CLADDING | 84 0.001 m | 1166Sfl0000220402/02 | m² | Maler- und Lackierarbeiten | 2 | 0.001 | 0 | 1 | Seitenfläche | 84 | 0 | 0 | NEW | AllplanAttributes - Bezeichnung: Acrovyn
Gipsfaserplatten 2-lagig (BSK) | WUN-H2-E01-046 | CEILING | layer 0.036 m | 1166Dfl0000033614/01 | m² | Trockenbauarbeiten | 1 | 0.036 | 0 | 1 | Deckenfläche |  | 0 | 0 | NEW | 2.5 | AllplanAttributes - Bezeichnung: Gipsfaserplatten 2-lagig (BSK); RoomName: Einzelzimmer mit Zustelloption
Gipsfaserplatten 2-lagig (BSK) | WUN-H2-E01-046 | CEILING | Installationshöhe 0.764 m | 1166Dfl0000033614/02 | m² | Trockenbauarbeiten | 2 | 0.764 | 0 | 1 | Bekleidung | Installationshöhe | 0 | 0 | NEW | 2.5 | AllplanAttributes - ash_lichte Raumhöhe: 2.500000; OKFF: 0; RoomName: Einzelzimmer mit Zustelloption
Gipsfaserplatten 2-lagig (BSK) | WUN-H2-E01-046 | CEILING | A1 0.1 m | 1166Dfl0000033614/03 | m² | Trockenbauarbeiten | 3 | 0.1 | 0 | 1 | Bekleidung | A1 | 0 | 0 | NEW | 2.5 | AllplanAttributes - ash_lichte Raumhöhe: 2.500000; OKFF: 0; RoomName: Einzelzimmer mit Zustelloption; Pset_CoveringCommon - AcousticRating: -
Gipsfaserplatten 2-lagig (BSK) | WUN-H2-E01-046 | CEILING | D1 0.001 m | 1166Dfl0000033614/04 | m² | Maler- und Lackierarbeiten | 4 | 0.001 | 0 | 1 | Bekleidung | D1 | 0 | 0 | NEW | 2.5 | AllplanAttributes - ash_lichte Raumhöhe: 2.500000; OKFF: 0; RoomName: Einzelzimmer mit Zustelloption
PVC Bahnenware Holzoptik | WUN-H2-E01-046 | FLOORING | Ku1 0.15 m | 1166Bfl0000033603/01 | m² | Bodenbelagsarbeiten | 1 | 0.15 | 0 | 1 | Bodenfläche | Ku1 | 0 | 0 | NEW | AllplanAttributes - Bezeichnung: PVC Bahnenware Holzoptik; Raumnr. Bauherr: 2.11_A2_02; ash B_Aufbau: B9; ash B_Rutschhemmung: R9
Gipsfaserplatten 2-lagig (BSK) | WUN-H2-E01-046 | CEILING | layer 0.036 m | 1166Dfl0000033604/01 | m² | Trockenbauarbeiten | 1 | 0.036 | 0 | 1 | Deckenfläche |  | 0 | 0 | NEW | 3.15 | AllplanAttributes - Bezeichnung: Gipsfaserplatten 2-lagig (BSK); RoomName: Doppelzimmer
Gipsfaserplatten 2-lagig (BSK) | WUN-H2-E01-046 | CEILING | Installationshöhe 0.114 m | 1166Dfl0000033604/02 | m² | Trockenbauarbeiten | 2 | 0.114 | 0 | 1 | Bekleidung | Installationshöhe | 0 | 0 | NEW | 3.15 | AllplanAttributes - ash_lichte Raumhöhe: 3.150000; RoomName: Doppelzimmer; Pset_CoveringCommon - AcousticRating: -
Gipsfaserplatten 2-lagig (BSK) | WUN-H2-E01-046 | CEILING | A1 0.1 m | 1166Dfl0000033604/03 | m² | Trockenbauarbeiten | 3 | 0.1 | 0 | 1 | Bekleidung | A1 | 0 | 0 | NEW | 3.15 | AllplanAttributes - ash_lichte Raumhöhe: 3.150000; RoomName: Doppelzimmer; Pset_CoveringCommon - AcousticRating: -
Gipsfaserplatten 2-lagig (BSK) | WUN-H2-E01-046 | CEILING | D1 0.001 m | 1166Dfl0000033604/04 | m² | Maler- und Lackierarbeiten | 4 | 0.001 | 0 | 1 | Bekleidung | D1 | 0 | 0 | NEW | 3.15 | AllplanAttributes - ash_lichte Raumhöhe: 3.150000; RoomName: Doppelzimmer
 | WUN-H2-E01-046 | CLADDING | 49 0.001 m | 1166Sfl0000665040/01 | m² | Maler- und Lackierarbeiten | 1 | 0.001 | 0 | 1 | Seitenfläche | 49 | 150 | 3150 | NEW
Acrovyn | WUN-H2-E01-045 | CLADDING | 84 0.001 m | 1166Sfl0000220362/02 | m² | Maler- und Lackierarbeiten | 2 | 0.001 | 0 | 1 | Seitenfläche | 84 | 0 | 0 | NEW | AllplanAttributes - Bezeichnung: Acrovyn
Acrovyn | WUN-H2-E01-045 | CLADDING | 84 0.001 m | 1166Sfl0000220400/02 | m² | Maler- und Lackierarbeiten | 2 | 0.001 | 0 | 1 | Seitenfläche | 84 | 0 | 0 | NEW | AllplanAttributes - Bezeichnung: Acrovyn
Gipsfaserplatten 2-lagig (BSK) | WUN-H2-E01-045 | CEILING | layer 0.036 m | 1166Dfl0000033601/01 | m² | Trockenbauarbeiten | 1 | 0.036 | 0 | 1 | Deckenfläche |  | 0 | 0 | NEW | 2.5 | AllplanAttributes - Bezeichnung: Gipsfaserplatten 2-lagig (BSK); RoomName: Doppelzimmer
Gipsfaserplatten 2-lagig (BSK) | WUN-H2-E01-045 | CEILING | Installationshöhe 0.764 m | 1166Dfl0000033601/02 | m² | Trockenbauarbeiten | 2 | 0.764 | 0 | 1 | Bekleidung | Installationshöhe | 0 | 0 | NEW | 2.5 | AllplanAttributes - ash_lichte Raumhöhe: 2.500000; OKFF: 0; RoomName: Doppelzimmer
Gipsfaserplatten 2-lagig (BSK) | WUN-H2-E01-045 | CEILING | A1 0.1 m | 1166Dfl0000033601/03 | m² | Trockenbauarbeiten | 3 | 0.1 | 0 | 1 | Bekleidung | A1 | 0 | 0 | NEW | 2.5 | AllplanAttributes - ash_lichte Raumhöhe: 2.500000; OKFF: 0; RoomName: Doppelzimmer; Pset_CoveringCommon - AcousticRating: -
Gipsfaserplatten 2-lagig (BSK) | WUN-H2-E01-045 | CEILING | D1 0.001 m | 1166Dfl0000033601/04 | m² | Maler- und Lackierarbeiten | 4 | 0.001 | 0 | 1 | Bekleidung | D1 | 0 | 0 | NEW | 2.5 | AllplanAttributes - ash_lichte Raumhöhe: 2.500000; OKFF: 0; RoomName: Doppelzimmer
PVC Bahnenware Holzoptik | WUN-H2-E01-045 | FLOORING | Ku1 0.15 m | 1166Bfl0000033590/01 | m² | Bodenbelagsarbeiten | 1 | 0.15 | 0 | 1 | Bodenfläche | Ku1 | 0 | 0 | NEW | AllplanAttributes - Bezeichnung: PVC Bahnenware Holzoptik; Raumnr. Bauherr: 2.11_A2_02; ash B_Aufbau: B9; ash B_Rutschhemmung: R9
Gipsfaserplatten 2-lagig (BSK) | WUN-H2-E01-045 | CEILING | layer 0.036 m | 1166Dfl0000033591/01 | m² | Trockenbauarbeiten | 1 | 0.036 | 0 | 1 | Deckenfläche |  | 0 | 0 | NEW | 3.15 | AllplanAttributes - Bezeichnung: Gipsfaserplatten 2-lagig (BSK); RoomName: Doppelzimmer
Gipsfaserplatten 2-lagig (BSK) | WUN-H2-E01-045 | CEILING | Installationshöhe 0.114 m | 1166Dfl0000033591/02 | m² | Trockenbauarbeiten | 2 | 0.114 | 0 | 1 | Bekleidung | Installationshöhe | 0 | 0 | NEW | 3.15 | AllplanAttributes - ash_lichte Raumhöhe: 3.150000; RoomName: Doppelzimmer; Pset_CoveringCommon - AcousticRating: -
Gipsfaserplatten 2-lagig (BSK) | WUN-H2-E01-045 | CEILING | A1 0.1 m | 1166Dfl0000033591/03 | m² | Trockenbauarbeiten | 3 | 0.1 | 0 | 1 | Bekleidung | A1 | 0 | 0 | NEW | 3.15 | AllplanAttributes - ash_lichte Raumhöhe: 3.150000; RoomName: Doppelzimmer; Pset_CoveringCommon - AcousticRating: -
Gipsfaserplatten 2-lagig (BSK) | WUN-H2-E01-045 | CEILING | D1 0.001 m | 1166Dfl0000033591/04 | m² | Maler- und Lackierarbeiten | 4 | 0.001 | 0 | 1 | Bekleidung | D1 | 0 | 0 | NEW | 3.15 | AllplanAttributes - ash_lichte Raumhöhe: 3.150000; RoomName: Doppelzimmer
 | WUN-H2-E01-045 | CLADDING | 49 0.001 m | 1166Sfl0000665041/01 | m² | Maler- und Lackierarbeiten | 1 | 0.001 | 0 | 1 | Seitenfläche | 49 | 150 | 3150 | NEW
Acrovyn | WUN-H2-E01-044 | CLADDING | 84 0.001 m | 1166Sfl0000220360/02 | m² | Maler- und Lackierarbeiten | 2 | 0.001 | 0 | 1 | Seitenfläche | 84 | 0 | 0 | NEW | AllplanAttributes - Bezeichnung: Acrovyn
Gipsfaserplatten 2-lagig (BSK) | WUN-H2-E01-044 | CEILING | layer 0.036 m | 1166Dfl0000033588/01 | m² | Trockenbauarbeiten | 1 | 0.036 | 0 | 1 | Deckenfläche |  | 0 | 0 | NEW | 2.5 | AllplanAttributes - Bezeichnung: Gipsfaserplatten 2-lagig (BSK); RoomName: Einzelzimmer
Gipsfaserplatten 2-lagig (BSK) | WUN-H2-E01-044 | CEILING | Installationshöhe 0.764 m | 1166Dfl0000033588/02 | m² | Trockenbauarbeiten | 2 | 0.764 | 0 | 1 | Bekleidung | Installationshöhe | 0 | 0 | NEW | 2.5 | AllplanAttributes - ash_lichte Raumhöhe: 2.500000; OKFF: 0; RoomName: Einzelzimmer
Gipsfaserplatten 2-lagig (BSK) | WUN-H2-E01-044 | CEILING | A1 0.1 m | 1166Dfl0000033588/03 | m² | Trockenbauarbeiten | 3 | 0.1 | 0 | 1 | Bekleidung | A1 | 0 | 0 | NEW | 2.5 | AllplanAttributes - ash_lichte Raumhöhe: 2.500000; OKFF: 0; RoomName: Einzelzimmer; Pset_CoveringCommon - AcousticRating: -
Gipsfaserplatten 2-lagig (BSK) | WUN-H2-E01-044 | CEILING | D1 0.001 m | 1166Dfl0000033588/04 | m² | Maler- und Lackierarbeiten | 4 | 0.001 | 0 | 1 | Bekleidung | D1 | 0 | 0 | NEW | 2.5 | AllplanAttributes - ash_lichte Raumhöhe: 2.500000; OKFF: 0; RoomName: Einzelzimmer
PVC Bahnenware Holzoptik | WUN-H2-E01-044 | FLOORING | Ku1 0.15 m | 1166Bfl0000033577/01 | m² | Bodenbelagsarbeiten | 1 | 0.15 | 0 | 1 | Bodenfläche | Ku1 | 0 | 0 | NEW | AllplanAttributes - Bezeichnung: PVC Bahnenware Holzoptik; Raumnr. Bauherr: 2.11_A2_02; ash B_Aufbau: B9; ash B_Rutschhemmung: R9
Gipsfaserplatten 2-lagig (BSK) | WUN-H2-E01-044 | CEILING | layer 0.036 m | 1166Dfl0000033578/01 | m² | Trockenbauarbeiten | 1 | 0.036 | 0 | 1 | Deckenfläche |  | 0 | 0 | NEW | 3.15 | AllplanAttributes - Bezeichnung: Gipsfaserplatten 2-lagig (BSK); RoomName: Doppelzimmer
Gipsfaserplatten 2-lagig (BSK) | WUN-H2-E01-044 | CEILING | Installationshöhe 0.114 m | 1166Dfl0000033578/02 | m² | Trockenbauarbeiten | 2 | 0.114 | 0 | 1 | Bekleidung | Installationshöhe | 0 | 0 | NEW | 3.15 | AllplanAttributes - ash_lichte Raumhöhe: 3.150000; RoomName: Doppelzimmer; Pset_CoveringCommon - AcousticRating: -
Gipsfaserplatten 2-lagig (BSK) | WUN-H2-E01-044 | CEILING | A1 0.1 m | 1166Dfl0000033578/03 | m² | Trockenbauarbeiten | 3 | 0.1 | 0 | 1 | Bekleidung | A1 | 0 | 0 | NEW | 3.15 | AllplanAttributes - ash_lichte Raumhöhe: 3.150000; RoomName: Doppelzimmer; Pset_CoveringCommon - AcousticRating: -
Gipsfaserplatten 2-lagig (BSK) | WUN-H2-E01-044 | CEILING | D1 0.001 m | 1166Dfl0000033578/04 | m² | Maler- und Lackierarbeiten | 4 | 0.001 | 0 | 1 | Bekleidung | D1 | 0 | 0 | NEW | 3.15 | AllplanAttributes - ash_lichte Raumhöhe: 3.150000; RoomName: Doppelzimmer
 | WUN-H2-E01-044 | CLADDING | 49 0.001 m | 1166Sfl0000665042/01 | m² | Maler- und Lackierarbeiten | 1 | 0.001 | 0 | 1 | Seitenfläche | 49 | 150 | 3150 | NEW
Acrovyn | WUN-H2-E01-042 | CLADDING | 84 0.001 m | 1166Sfl0000220348/02 | m² | Maler- und Lackierarbeiten | 2 | 0.001 | 0 | 1 | Seitenfläche | 84 | 0 | 0 | NEW | AllplanAttributes - Bezeichnung: Acrovyn
Acrovyn | WUN-H2-E01-042 | CLADDING | 84 0.001 m | 1166Sfl0000220354/02 | m² | Maler- und Lackierarbeiten | 2 | 0.001 | 0 | 1 | Seitenfläche | 84 | 0 | 0 | NEW | AllplanAttributes - Bezeichnung: Acrovyn
Gipsfaserplatten 2-lagig (BSK) | WUN-H2-E01-042 | CEILING | layer 0.036 m | 1166Dfl0000033562/01 | m² | Trockenbauarbeiten | 1 | 0.036 | 0 | 1 | Deckenfläche |  | 0 | 0 | NEW | 2.5 | AllplanAttributes - Bezeichnung: Gipsfaserplatten 2-lagig (BSK); RoomName: Ruheraum
Gipsfaserplatten 2-lagig (BSK) | WUN-H2-E01-042 | CEILING | Installationshöhe 0.764 m | 1166Dfl0000033562/02 | m² | Trockenbauarbeiten | 2 | 0.764 | 0 | 1 | Bekleidung | Installationshöhe | 0 | 0 | NEW | 2.5 | AllplanAttributes - ash_lichte Raumhöhe: 2.500000; OKFF: 0; RoomName: Ruheraum
Gipsfaserplatten 2-lagig (BSK) | WUN-H2-E01-042 | CEILING | A1 0.1 m | 1166Dfl0000033562/03 | m² | Trockenbauarbeiten | 3 | 0.1 | 0 | 1 | Bekleidung | A1 | 0 | 0 | NEW | 2.5 | AllplanAttributes - ash_lichte Raumhöhe: 2.500000; OKFF: 0; RoomName: Ruheraum; Pset_CoveringCommon - AcousticRating: -
Gipsfaserplatten 2-lagig (BSK) | WUN-H2-E01-042 | CEILING | D1 0.001 m | 1166Dfl0000033562/04 | m² | Maler- und Lackierarbeiten | 4 | 0.001 | 0 | 1 | Bekleidung | D1 | 0 | 0 | NEW | 2.5 | AllplanAttributes - ash_lichte Raumhöhe: 2.500000; OKFF: 0; RoomName: Ruheraum
PVC Bahnenware Holzoptik | WUN-H2-E01-042 | FLOORING | Ku1 0.15 m | 1166Bfl0000033551/01 | m² | Bodenbelagsarbeiten | 1 | 0.15 | 0 | 1 | Bodenfläche | Ku1 | 0 | 0 | NEW | AllplanAttributes - Bezeichnung: PVC Bahnenware Holzoptik; Raumnr. Bauherr: 2.11_A2_02; ash B_Aufbau: B9; ash B_Rutschhemmung: R9
Gipsfaserplatten 2-lagig (BSK) | WUN-H2-E01-042 | CEILING | layer 0.036 m | 1166Dfl0000033552/01 | m² | Trockenbauarbeiten | 1 | 0.036 | 0 | 1 | Deckenfläche |  | 0 | 0 | NEW | 3.15 | AllplanAttributes - Bezeichnung: Gipsfaserplatten 2-lagig (BSK); RoomName: Doppelzimmer
Gipsfaserplatten 2-lagig (BSK) | WUN-H2-E01-042 | CEILING | Installationshöhe 0.114 m | 1166Dfl0000033552/02 | m² | Trockenbauarbeiten | 2 | 0.114 | 0 | 1 | Bekleidung | Installationshöhe | 0 | 0 | NEW | 3.15 | AllplanAttributes - ash_lichte Raumhöhe: 3.150000; RoomName: Doppelzimmer; Pset_CoveringCommon - AcousticRating: -
Gipsfaserplatten 2-lagig (BSK) | WUN-H2-E01-042 | CEILING | A1 0.1 m | 1166Dfl0000033552/03 | m² | Trockenbauarbeiten | 3 | 0.1 | 0 | 1 | Bekleidung | A1 | 0 | 0 | NEW | 3.15 | AllplanAttributes - ash_lichte Raumhöhe: 3.150000; RoomName: Doppelzimmer; Pset_CoveringCommon - AcousticRating: -
Gipsfaserplatten 2-lagig (BSK) | WUN-H2-E01-042 | CEILING | D1 0.001 m | 1166Dfl0000033552/04 | m² | Maler- und Lackierarbeiten | 4 | 0.001 | 0 | 1 | Bekleidung | D1 | 0 | 0 | NEW | 3.15 | AllplanAttributes - ash_lichte Raumhöhe: 3.150000; RoomName: Doppelzimmer
 | WUN-H2-E01-042 | CLADDING | 49 0.001 m | 1166Sfl0000665043/01 | m² | Maler- und Lackierarbeiten | 1 | 0.001 | 0 | 1 | Seitenfläche | 49 | 150 | 3150 | NEW
Acrovyn | WUN-H2-E01-043 | CLADDING | 84 0.001 m | 1166Sfl0000220356/02 | m² | Maler- und Lackierarbeiten | 2 | 0.001 | 0 | 1 | Seitenfläche | 84 | 0 | 0 | NEW | AllplanAttributes - Bezeichnung: Acrovyn
Acrovyn | WUN-H2-E01-043 | CLADDING | 84 0.001 m | 1166Sfl0000220404/02 | m² | Maler- und Lackierarbeiten | 2 | 0.001 | 0 | 1 | Seitenfläche | 84 | 0 | 0 | NEW | AllplanAttributes - Bezeichnung: Acrovyn
Gipsfaserplatten 2-lagig (BSK) | WUN-H2-E01-043 | CEILING | layer 0.036 m | 1166Dfl0000033575/01 | m² | Trockenbauarbeiten | 1 | 0.036 | 0 | 1 | Deckenfläche |  | 0 | 0 | NEW | 2.5 | AllplanAttributes - Bezeichnung: Gipsfaserplatten 2-lagig (BSK); RoomName: Rollstuhlgerechtes Doppelzimmer
Gipsfaserplatten 2-lagig (BSK) | WUN-H2-E01-043 | CEILING | Installationshöhe 0.764 m | 1166Dfl0000033575/02 | m² | Trockenbauarbeiten | 2 | 0.764 | 0 | 1 | Bekleidung | Installationshöhe | 0 | 0 | NEW | 2.5 | AllplanAttributes - ash_lichte Raumhöhe: 2.500000; OKFF: 0; RoomName: Rollstuhlgerechtes Doppelzimmer
Gipsfaserplatten 2-lagig (BSK) | WUN-H2-E01-043 | CEILING | A1 0.1 m | 1166Dfl0000033575/03 | m² | Trockenbauarbeiten | 3 | 0.1 | 0 | 1 | Bekleidung | A1 | 0 | 0 | NEW | 2.5 | AllplanAttributes - ash_lichte Raumhöhe: 2.500000; OKFF: 0; RoomName: Rollstuhlgerechtes Doppelzimmer; Pset_CoveringCommon - AcousticRating: -
Gipsfaserplatten 2-lagig (BSK) | WUN-H2-E01-043 | CEILING | D1 0.001 m | 1166Dfl0000033575/04 | m² | Maler- und Lackierarbeiten | 4 | 0.001 | 0 | 1 | Bekleidung | D1 | 0 | 0 | NEW | 2.5 | AllplanAttributes - ash_lichte Raumhöhe: 2.500000; OKFF: 0; RoomName: Rollstuhlgerechtes Doppelzimmer
PVC Bahnenware Holzoptik | WUN-H2-E01-043 | FLOORING | Ku1 0.15 m | 1166Bfl0000033564/01 | m² | Bodenbelagsarbeiten | 1 | 0.15 | 0 | 1 | Bodenfläche | Ku1 | 0 | 0 | NEW | AllplanAttributes - Bezeichnung: PVC Bahnenware Holzoptik; Raumnr. Bauherr: 2.11_A2_02; ash B_Aufbau: B9; ash B_Rutschhemmung: R9
Gipsfaserplatten 2-lagig (BSK) | WUN-H2-E01-043 | CEILING | layer 0.036 m | 1166Dfl0000033565/01 | m² | Trockenbauarbeiten | 1 | 0.036 | 0 | 1 | Deckenfläche |  | 0 | 0 | NEW | 3.15 | AllplanAttributes - Bezeichnung: Gipsfaserplatten 2-lagig (BSK); RoomName: Doppelzimmer
Gipsfaserplatten 2-lagig (BSK) | WUN-H2-E01-043 | CEILING | Installationshöhe 0.114 m | 1166Dfl0000033565/02 | m² | Trockenbauarbeiten | 2 | 0.114 | 0 | 1 | Bekleidung | Installationshöhe | 0 | 0 | NEW | 3.15 | AllplanAttributes - ash_lichte Raumhöhe: 3.150000; RoomName: Doppelzimmer; Pset_CoveringCommon - AcousticRating: -
Gipsfaserplatten 2-lagig (BSK) | WUN-H2-E01-043 | CEILING | A1 0.1 m | 1166Dfl0000033565/03 | m² | Trockenbauarbeiten | 3 | 0.1 | 0 | 1 | Bekleidung | A1 | 0 | 0 | NEW | 3.15 | AllplanAttributes - ash_lichte Raumhöhe: 3.150000; RoomName: Doppelzimmer; Pset_CoveringCommon - AcousticRating: -
Gipsfaserplatten 2-lagig (BSK) | WUN-H2-E01-043 | CEILING | D1 0.001 m | 1166Dfl0000033565/04 | m² | Maler- und Lackierarbeiten | 4 | 0.001 | 0 | 1 | Bekleidung | D1 | 0 | 0 | NEW | 3.15 | AllplanAttributes - ash_lichte Raumhöhe: 3.150000; RoomName: Doppelzimmer
 | WUN-H2-E01-043 | CLADDING | 49 0.001 m | 1166Sfl0000665044/01 | m² | Maler- und Lackierarbeiten | 1 | 0.001 | 0 | 1 | Seitenfläche | 49 | 150 | 3150 | NEW
Acrovyn | WUN-H2-E01-069 | CLADDING | 84 0.001 m | 1166Sfl0000220391/02 | m² | Maler- und Lackierarbeiten | 2 | 0.001 | 0 | 1 | Seitenfläche | 84 | 0 | 0 | NEW | AllplanAttributes - Bezeichnung: Acrovyn
Acrovyn | WUN-H2-E01-069 | CLADDING | 84 0.001 m | 1166Sfl0000220366/02 | m² | Maler- und Lackierarbeiten | 2 | 0.001 | 0 | 1 | Seitenfläche | 84 | 0 | 0 | NEW | AllplanAttributes - Bezeichnung: Acrovyn
Gipsfaserplatten 2-lagig (BSK) | WUN-H2-E01-069 | CEILING | layer 0.036 m | 1166Dfl0000033877/01 | m² | Trockenbauarbeiten | 1 | 0.036 | 0 | 1 | Deckenfläche |  | 0 | 0 | NEW | 2.5 | AllplanAttributes - Bezeichnung: Gipsfaserplatten 2-lagig (BSK); RoomName: Einzelzimmer mit Zustelloption
Gipsfaserplatten 2-lagig (BSK) | WUN-H2-E01-069 | CEILING | Installationshöhe 0.764 m | 1166Dfl0000033877/02 | m² | Trockenbauarbeiten | 2 | 0.764 | 0 | 1 | Bekleidung | Installationshöhe | 0 | 0 | NEW | 2.5 | AllplanAttributes - ash_lichte Raumhöhe: 2.500000; OKFF: 0; RoomName: Einzelzimmer mit Zustelloption
Gipsfaserplatten 2-lagig (BSK) | WUN-H2-E01-069 | CEILING | A1 0.1 m | 1166Dfl0000033877/03 | m² | Trockenbauarbeiten | 3 | 0.1 | 0 | 1 | Bekleidung | A1 | 0 | 0 | NEW | 2.5 | AllplanAttributes - ash_lichte Raumhöhe: 2.500000; OKFF: 0; RoomName: Einzelzimmer mit Zustelloption; Pset_CoveringCommon - AcousticRating: -
Gipsfaserplatten 2-lagig (BSK) | WUN-H2-E01-069 | CEILING | D1 0.001 m | 1166Dfl0000033877/04 | m² | Maler- und Lackierarbeiten | 4 | 0.001 | 0 | 1 | Bekleidung | D1 | 0 | 0 | NEW | 2.5 | AllplanAttributes - ash_lichte Raumhöhe: 2.500000; OKFF: 0; RoomName: Einzelzimmer mit Zustelloption
PVC Bahnenware Holzoptik | WUN-H2-E01-069 | FLOORING | Ku1 0.15 m | 1166Bfl0000033866/01 | m² | Bodenbelagsarbeiten | 1 | 0.15 | 0 | 1 | Bodenfläche | Ku1 | 0 | 0 | NEW | AllplanAttributes - Bezeichnung: PVC Bahnenware Holzoptik; Raumnr. Bauherr: 2.11_A2_02; ash B_Aufbau: B9; ash B_Rutschhemmung: R9
Gipsfaserplatten 2-lagig (BSK) | WUN-H2-E01-069 | CEILING | layer 0.036 m | 1166Dfl0000033867/01 | m² | Trockenbauarbeiten | 1 | 0.036 | 0 | 1 | Deckenfläche |  | 0 | 0 | NEW | 3.15 | AllplanAttributes - Bezeichnung: Gipsfaserplatten 2-lagig (BSK); RoomName: Doppelzimmer
Gipsfaserplatten 2-lagig (BSK) | WUN-H2-E01-069 | CEILING | Installationshöhe 0.114 m | 1166Dfl0000033867/02 | m² | Trockenbauarbeiten | 2 | 0.114 | 0 | 1 | Bekleidung | Installationshöhe | 0 | 0 | NEW | 3.15 | AllplanAttributes - ash_lichte Raumhöhe: 3.150000; RoomName: Doppelzimmer; Pset_CoveringCommon - AcousticRating: -
Gipsfaserplatten 2-lagig (BSK) | WUN-H2-E01-069 | CEILING | A1 0.1 m | 1166Dfl0000033867/03 | m² | Trockenbauarbeiten | 3 | 0.1 | 0 | 1 | Bekleidung | A1 | 0 | 0 | NEW | 3.15 | AllplanAttributes - ash_lichte Raumhöhe: 3.150000; RoomName: Doppelzimmer; Pset_CoveringCommon - AcousticRating: -
Gipsfaserplatten 2-lagig (BSK) | WUN-H2-E01-069 | CEILING | D1 0.001 m | 1166Dfl0000033867/04 | m² | Maler- und Lackierarbeiten | 4 | 0.001 | 0 | 1 | Bekleidung | D1 | 0 | 0 | NEW | 3.15 | AllplanAttributes - ash_lichte Raumhöhe: 3.150000; RoomName: Doppelzimmer
 | WUN-H2-E01-069 | CLADDING | 49 0.001 m | 1166Sfl0000665045/01 | m² | Maler- und Lackierarbeiten | 1 | 0.001 | 0 | 1 | Seitenfläche | 49 | 150 | 3150 | NEW
Acrovyn | WUN-H2-E01-074 | CLADDING | 84 0.001 m | 1166Sfl0000220378/02 | m² | Maler- und Lackierarbeiten | 2 | 0.001 | 0 | 1 | Seitenfläche | 84 | 0 | 0 | NEW | AllplanAttributes - Bezeichnung: Acrovyn
Acrovyn | WUN-H2-E01-074 | CLADDING | 84 0.001 m | 1166Sfl0000220376/02 | m² | Maler- und Lackierarbeiten | 2 | 0.001 | 0 | 1 | Seitenfläche | 84 | 0 | 0 | NEW | AllplanAttributes - Bezeichnung: Acrovyn
Gipsfaserplatten 2-lagig (BSK) | WUN-H2-E01-074 | CEILING | layer 0.036 m | 1166Dfl0000033942/01 | m² | Trockenbauarbeiten | 1 | 0.036 | 0 | 1 | Deckenfläche |  | 0 | 0 | NEW | 2.5 | AllplanAttributes - Bezeichnung: Gipsfaserplatten 2-lagig (BSK); RoomName: Ruheraum
Gipsfaserplatten 2-lagig (BSK) | WUN-H2-E01-074 | CEILING | Installationshöhe 0.764 m | 1166Dfl0000033942/02 | m² | Trockenbauarbeiten | 2 | 0.764 | 0 | 1 | Bekleidung | Installationshöhe | 0 | 0 | NEW | 2.5 | AllplanAttributes - ash_lichte Raumhöhe: 2.500000; OKFF: 0; RoomName: Ruheraum
Gipsfaserplatten 2-lagig (BSK) | WUN-H2-E01-074 | CEILING | A1 0.1 m | 1166Dfl0000033942/03 | m² | Trockenbauarbeiten | 3 | 0.1 | 0 | 1 | Bekleidung | A1 | 0 | 0 | NEW | 2.5 | AllplanAttributes - ash_lichte Raumhöhe: 2.500000; OKFF: 0; RoomName: Ruheraum; Pset_CoveringCommon - AcousticRating: -
Gipsfaserplatten 2-lagig (BSK) | WUN-H2-E01-074 | CEILING | D1 0.001 m | 1166Dfl0000033942/04 | m² | Maler- und Lackierarbeiten | 4 | 0.001 | 0 | 1 | Bekleidung | D1 | 0 | 0 | NEW | 2.5 | AllplanAttributes - ash_lichte Raumhöhe: 2.500000; OKFF: 0; RoomName: Ruheraum
PVC Bahnenware Holzoptik | WUN-H2-E01-074 | FLOORING | Ku1 0.15 m | 1166Bfl0000033931/01 | m² | Bodenbelagsarbeiten | 1 | 0.15 | 0 | 1 | Bodenfläche | Ku1 | 0 | 0 | NEW | AllplanAttributes - Bezeichnung: PVC Bahnenware Holzoptik; Raumnr. Bauherr: 2.11_A2_02; ash B_Aufbau: B9; ash B_Rutschhemmung: R9
Gipsfaserplatten 2-lagig (BSK) | WUN-H2-E01-074 | CEILING | layer 0.036 m | 1166Dfl0000033932/01 | m² | Trockenbauarbeiten | 1 | 0.036 | 0 | 1 | Deckenfläche |  | 0 | 0 | NEW | 3.15 | AllplanAttributes - Bezeichnung: Gipsfaserplatten 2-lagig (BSK); RoomName: Doppelzimmer
Gipsfaserplatten 2-lagig (BSK) | WUN-H2-E01-074 | CEILING | Installationshöhe 0.114 m | 1166Dfl0000033932/02 | m² | Trockenbauarbeiten | 2 | 0.114 | 0 | 1 | Bekleidung | Installationshöhe | 0 | 0 | NEW | 3.15 | AllplanAttributes - ash_lichte Raumhöhe: 3.150000; RoomName: Doppelzimmer; Pset_CoveringCommon - AcousticRating: -
Gipsfaserplatten 2-lagig (BSK) | WUN-H2-E01-074 | CEILING | A1 0.1 m | 1166Dfl0000033932/03 | m² | Trockenbauarbeiten | 3 | 0.1 | 0 | 1 | Bekleidung | A1 | 0 | 0 | NEW | 3.15 | AllplanAttributes - ash_lichte Raumhöhe: 3.150000; RoomName: Doppelzimmer; Pset_CoveringCommon - AcousticRating: -
Gipsfaserplatten 2-lagig (BSK) | WUN-H2-E01-074 | CEILING | D1 0.001 m | 1166Dfl0000033932/04 | m² | Maler- und Lackierarbeiten | 4 | 0.001 | 0 | 1 | Bekleidung | D1 | 0 | 0 | NEW | 3.15 | AllplanAttributes - ash_lichte Raumhöhe: 3.150000; RoomName: Doppelzimmer
 | WUN-H2-E01-074 | CLADDING | 49 0.001 m | 1166Sfl0000665046/01 | m² | Maler- und Lackierarbeiten | 1 | 0.001 | 0 | 1 | Seitenfläche | 49 | 150 | 3150 | NEW
Acrovyn | WUN-H2-E01-073 | CLADDING | 84 0.001 m | 1166Sfl0000220372/02 | m² | Maler- und Lackierarbeiten | 2 | 0.001 | 0 | 1 | Seitenfläche | 84 | 0 | 0 | NEW | AllplanAttributes - Bezeichnung: Acrovyn
Acrovyn | WUN-H2-E01-073 | CLADDING | 84 0.001 m | 1166Sfl0000220381/02 | m² | Maler- und Lackierarbeiten | 2 | 0.001 | 0 | 1 | Seitenfläche | 84 | 0 | 0 | NEW | AllplanAttributes - Bezeichnung: Acrovyn
Gipsfaserplatten 2-lagig (BSK) | WUN-H2-E01-073 | CEILING | layer 0.036 m | 1166Dfl0000033929/01 | m² | Trockenbauarbeiten | 1 | 0.036 | 0 | 1 | Deckenfläche |  | 0 | 0 | NEW | 2.5 | AllplanAttributes - Bezeichnung: Gipsfaserplatten 2-lagig (BSK); RoomName: Ruheraum
Gipsfaserplatten 2-lagig (BSK) | WUN-H2-E01-073 | CEILING | Installationshöhe 0.764 m | 1166Dfl0000033929/02 | m² | Trockenbauarbeiten | 2 | 0.764 | 0 | 1 | Bekleidung | Installationshöhe | 0 | 0 | NEW | 2.5 | AllplanAttributes - ash_lichte Raumhöhe: 2.500000; OKFF: 0; RoomName: Ruheraum
Gipsfaserplatten 2-lagig (BSK) | WUN-H2-E01-073 | CEILING | A1 0.1 m | 1166Dfl0000033929/03 | m² | Trockenbauarbeiten | 3 | 0.1 | 0 | 1 | Bekleidung | A1 | 0 | 0 | NEW | 2.5 | AllplanAttributes - ash_lichte Raumhöhe: 2.500000; OKFF: 0; RoomName: Ruheraum; Pset_CoveringCommon - AcousticRating: -
Gipsfaserplatten 2-lagig (BSK) | WUN-H2-E01-073 | CEILING | D1 0.001 m | 1166Dfl0000033929/04 | m² | Maler- und Lackierarbeiten | 4 | 0.001 | 0 | 1 | Bekleidung | D1 | 0 | 0 | NEW | 2.5 | AllplanAttributes - ash_lichte Raumhöhe: 2.500000; OKFF: 0; RoomName: Ruheraum
PVC Bahnenware Holzoptik | WUN-H2-E01-073 | FLOORING | Ku1 0.15 m | 1166Bfl0000033918/01 | m² | Bodenbelagsarbeiten | 1 | 0.15 | 0 | 1 | Bodenfläche | Ku1 | 0 | 0 | NEW | AllplanAttributes - Bezeichnung: PVC Bahnenware Holzoptik; Raumnr. Bauherr: 2.11_A2_02; ash B_Aufbau: B9; ash B_Rutschhemmung: R9
Gipsfaserplatten 2-lagig (BSK) | WUN-H2-E01-073 | CEILING | layer 0.036 m | 1166Dfl0000033919/01 | m² | Trockenbauarbeiten | 1 | 0.036 | 0 | 1 | Deckenfläche |  | 0 | 0 | NEW | 3.15 | AllplanAttributes - Bezeichnung: Gipsfaserplatten 2-lagig (BSK); RoomName: Doppelzimmer
Gipsfaserplatten 2-lagig (BSK) | WUN-H2-E01-073 | CEILING | Installationshöhe 0.114 m | 1166Dfl0000033919/02 | m² | Trockenbauarbeiten | 2 | 0.114 | 0 | 1 | Bekleidung | Installationshöhe | 0 | 0 | NEW | 3.15 | AllplanAttributes - ash_lichte Raumhöhe: 3.150000; RoomName: Doppelzimmer; Pset_CoveringCommon - AcousticRating: -
Gipsfaserplatten 2-lagig (BSK) | WUN-H2-E01-073 | CEILING | A1 0.1 m | 1166Dfl0000033919/03 | m² | Trockenbauarbeiten | 3 | 0.1 | 0 | 1 | Bekleidung | A1 | 0 | 0 | NEW | 3.15 | AllplanAttributes - ash_lichte Raumhöhe: 3.150000; RoomName: Doppelzimmer; Pset_CoveringCommon - AcousticRating: -
Gipsfaserplatten 2-lagig (BSK) | WUN-H2-E01-073 | CEILING | D1 0.001 m | 1166Dfl0000033919/04 | m² | Maler- und Lackierarbeiten | 4 | 0.001 | 0 | 1 | Bekleidung | D1 | 0 | 0 | NEW | 3.15 | AllplanAttributes - ash_lichte Raumhöhe: 3.150000; RoomName: Doppelzimmer
 | WUN-H2-E01-073 | CLADDING | 49 0.001 m | 1166Sfl0000665047/01 | m² | Maler- und Lackierarbeiten | 1 | 0.001 | 0 | 1 | Seitenfläche | 49 | 150 | 3150 | NEW
Acrovyn | WUN-H2-E01-070 | CLADDING | 84 0.001 m | 1166Sfl0000220389/02 | m² | Maler- und Lackierarbeiten | 2 | 0.001 | 0 | 1 | Seitenfläche | 84 | 0 | 0 | NEW | AllplanAttributes - Bezeichnung: Acrovyn
Acrovyn | WUN-H2-E01-070 | CLADDING | 84 0.001 m | 1166Sfl0000220368/02 | m² | Maler- und Lackierarbeiten | 2 | 0.001 | 0 | 1 | Seitenfläche | 84 | 0 | 0 | NEW | AllplanAttributes - Bezeichnung: Acrovyn
Gipsfaserplatten 2-lagig (BSK) | WUN-H2-E01-070 | CEILING | layer 0.036 m | 1166Dfl0000033890/01 | m² | Trockenbauarbeiten | 1 | 0.036 | 0 | 1 | Deckenfläche |  | 0 | 0 | NEW | 2.5 | AllplanAttributes - Bezeichnung: Gipsfaserplatten 2-lagig (BSK); RoomName: Doppelzimmer
Gipsfaserplatten 2-lagig (BSK) | WUN-H2-E01-070 | CEILING | Installationshöhe 0.764 m | 1166Dfl0000033890/02 | m² | Trockenbauarbeiten | 2 | 0.764 | 0 | 1 | Bekleidung | Installationshöhe | 0 | 0 | NEW | 2.5 | AllplanAttributes - ash_lichte Raumhöhe: 2.500000; OKFF: 0; RoomName: Doppelzimmer
Gipsfaserplatten 2-lagig (BSK) | WUN-H2-E01-070 | CEILING | A1 0.1 m | 1166Dfl0000033890/03 | m² | Trockenbauarbeiten | 3 | 0.1 | 0 | 1 | Bekleidung | A1 | 0 | 0 | NEW | 2.5 | AllplanAttributes - ash_lichte Raumhöhe: 2.500000; OKFF: 0; RoomName: Doppelzimmer; Pset_CoveringCommon - AcousticRating: -
Gipsfaserplatten 2-lagig (BSK) | WUN-H2-E01-070 | CEILING | D1 0.001 m | 1166Dfl0000033890/04 | m² | Maler- und Lackierarbeiten | 4 | 0.001 | 0 | 1 | Bekleidung | D1 | 0 | 0 | NEW | 2.5 | AllplanAttributes - ash_lichte Raumhöhe: 2.500000; OKFF: 0; RoomName: Doppelzimmer
PVC Bahnenware Holzoptik | WUN-H2-E01-070 | FLOORING | Ku1 0.15 m | 1166Bfl0000033879/01 | m² | Bodenbelagsarbeiten | 1 | 0.15 | 0 | 1 | Bodenfläche | Ku1 | 0 | 0 | NEW | AllplanAttributes - Bezeichnung: PVC Bahnenware Holzoptik; Raumnr. Bauherr: 2.11_A2_02; ash B_Aufbau: B9; ash B_Rutschhemmung: R9
Gipsfaserplatten 2-lagig (BSK) | WUN-H2-E01-070 | CEILING | layer 0.036 m | 1166Dfl0000033880/01 | m² | Trockenbauarbeiten | 1 | 0.036 | 0 | 1 | Deckenfläche |  | 0 | 0 | NEW | 3.15 | AllplanAttributes - Bezeichnung: Gipsfaserplatten 2-lagig (BSK); RoomName: Doppelzimmer
Gipsfaserplatten 2-lagig (BSK) | WUN-H2-E01-070 | CEILING | Installationshöhe 0.114 m | 1166Dfl0000033880/02 | m² | Trockenbauarbeiten | 2 | 0.114 | 0 | 1 | Bekleidung | Installationshöhe | 0 | 0 | NEW | 3.15 | AllplanAttributes - ash_lichte Raumhöhe: 3.150000; RoomName: Doppelzimmer; Pset_CoveringCommon - AcousticRating: -
Gipsfaserplatten 2-lagig (BSK) | WUN-H2-E01-070 | CEILING | A1 0.1 m | 1166Dfl0000033880/03 | m² | Trockenbauarbeiten | 3 | 0.1 | 0 | 1 | Bekleidung | A1 | 0 | 0 | NEW | 3.15 | AllplanAttributes - ash_lichte Raumhöhe: 3.150000; RoomName: Doppelzimmer; Pset_CoveringCommon - AcousticRating: -
Gipsfaserplatten 2-lagig (BSK) | WUN-H2-E01-070 | CEILING | D1 0.001 m | 1166Dfl0000033880/04 | m² | Maler- und Lackierarbeiten | 4 | 0.001 | 0 | 1 | Bekleidung | D1 | 0 | 0 | NEW | 3.15 | AllplanAttributes - ash_lichte Raumhöhe: 3.150000; RoomName: Doppelzimmer
 | WUN-H2-E01-070 | CLADDING | 49 0.001 m | 1166Sfl0000665048/01 | m² | Maler- und Lackierarbeiten | 1 | 0.001 | 0 | 1 | Seitenfläche | 49 | 150 | 3150 | NEW
Acrovyn | WUN-H2-E01-072 | CLADDING | 84 0.001 m | 1166Sfl0000220383/02 | m² | Maler- und Lackierarbeiten | 2 | 0.001 | 0 | 1 | Seitenfläche | 84 | 0 | 0 | NEW | AllplanAttributes - Bezeichnung: Acrovyn
Acrovyn | WUN-H2-E01-072 | CLADDING | 84 0.001 m | 1166Sfl0000220370/02 | m² | Maler- und Lackierarbeiten | 2 | 0.001 | 0 | 1 | Seitenfläche | 84 | 0 | 0 | NEW | AllplanAttributes - Bezeichnung: Acrovyn
Gipsfaserplatten 2-lagig (BSK) | WUN-H2-E01-072 | CEILING | layer 0.036 m | 1166Dfl0000033916/01 | m² | Trockenbauarbeiten | 1 | 0.036 | 0 | 1 | Deckenfläche |  | 0 | 0 | NEW | 2.5 | AllplanAttributes - Bezeichnung: Gipsfaserplatten 2-lagig (BSK); RoomName: Rollstuhlgerechtes Doppelzimmer
Gipsfaserplatten 2-lagig (BSK) | WUN-H2-E01-072 | CEILING | Installationshöhe 0.764 m | 1166Dfl0000033916/02 | m² | Trockenbauarbeiten | 2 | 0.764 | 0 | 1 | Bekleidung | Installationshöhe | 0 | 0 | NEW | 2.5 | AllplanAttributes - ash_lichte Raumhöhe: 2.500000; OKFF: 0; RoomName: Rollstuhlgerechtes Doppelzimmer
Gipsfaserplatten 2-lagig (BSK) | WUN-H2-E01-072 | CEILING | A1 0.1 m | 1166Dfl0000033916/03 | m² | Trockenbauarbeiten | 3 | 0.1 | 0 | 1 | Bekleidung | A1 | 0 | 0 | NEW | 2.5 | AllplanAttributes - ash_lichte Raumhöhe: 2.500000; OKFF: 0; RoomName: Rollstuhlgerechtes Doppelzimmer; Pset_CoveringCommon - AcousticRating: -
Gipsfaserplatten 2-lagig (BSK) | WUN-H2-E01-072 | CEILING | D1 0.001 m | 1166Dfl0000033916/04 | m² | Maler- und Lackierarbeiten | 4 | 0.001 | 0 | 1 | Bekleidung | D1 | 0 | 0 | NEW | 2.5 | AllplanAttributes - ash_lichte Raumhöhe: 2.500000; OKFF: 0; RoomName: Rollstuhlgerechtes Doppelzimmer
PVC Bahnenware Holzoptik | WUN-H2-E01-072 | FLOORING | Ku1 0.15 m | 1166Bfl0000033905/01 | m² | Bodenbelagsarbeiten | 1 | 0.15 | 0 | 1 | Bodenfläche | Ku1 | 0 | 0 | NEW | AllplanAttributes - Bezeichnung: PVC Bahnenware Holzoptik; Raumnr. Bauherr: 2.11_A2_02; ash B_Aufbau: B9; ash B_Rutschhemmung: R9
Gipsfaserplatten 2-lagig (BSK) | WUN-H2-E01-072 | CEILING | layer 0.036 m | 1166Dfl0000033906/01 | m² | Trockenbauarbeiten | 1 | 0.036 | 0 | 1 | Deckenfläche |  | 0 | 0 | NEW | 3.15 | AllplanAttributes - Bezeichnung: Gipsfaserplatten 2-lagig (BSK); RoomName: Doppelzimmer
Gipsfaserplatten 2-lagig (BSK) | WUN-H2-E01-072 | CEILING | Installationshöhe 0.114 m | 1166Dfl0000033906/02 | m² | Trockenbauarbeiten | 2 | 0.114 | 0 | 1 | Bekleidung | Installationshöhe | 0 | 0 | NEW | 3.15 | AllplanAttributes - ash_lichte Raumhöhe: 3.150000; RoomName: Doppelzimmer; Pset_CoveringCommon - AcousticRating: -
Gipsfaserplatten 2-lagig (BSK) | WUN-H2-E01-072 | CEILING | A1 0.1 m | 1166Dfl0000033906/03 | m² | Trockenbauarbeiten | 3 | 0.1 | 0 | 1 | Bekleidung | A1 | 0 | 0 | NEW | 3.15 | AllplanAttributes - ash_lichte Raumhöhe: 3.150000; RoomName: Doppelzimmer; Pset_CoveringCommon - AcousticRating: -
Gipsfaserplatten 2-lagig (BSK) | WUN-H2-E01-072 | CEILING | D1 0.001 m | 1166Dfl0000033906/04 | m² | Maler- und Lackierarbeiten | 4 | 0.001 | 0 | 1 | Bekleidung | D1 | 0 | 0 | NEW | 3.15 | AllplanAttributes - ash_lichte Raumhöhe: 3.150000; RoomName: Doppelzimmer
 | WUN-H2-E01-072 | CLADDING | 49 0.001 m | 1166Sfl0000665049/01 | m² | Maler- und Lackierarbeiten | 1 | 0.001 | 0 | 1 | Seitenfläche | 49 | 150 | 3150 | NEW
Acrovyn | WUN-H2-E01-071 | CLADDING | 84 0.001 m | 1166Sfl0000220387/02 | m² | Maler- und Lackierarbeiten | 2 | 0.001 | 0 | 1 | Seitenfläche | 84 | 0 | 0 | NEW | AllplanAttributes - Bezeichnung: Acrovyn
Gipsfaserplatten 2-lagig (BSK) | WUN-H2-E01-071 | CEILING | layer 0.036 m | 1166Dfl0000033903/01 | m² | Trockenbauarbeiten | 1 | 0.036 | 0 | 1 | Deckenfläche |  | 0 | 0 | NEW | 2.5 | AllplanAttributes - Bezeichnung: Gipsfaserplatten 2-lagig (BSK); RoomName: Einzelzimmer
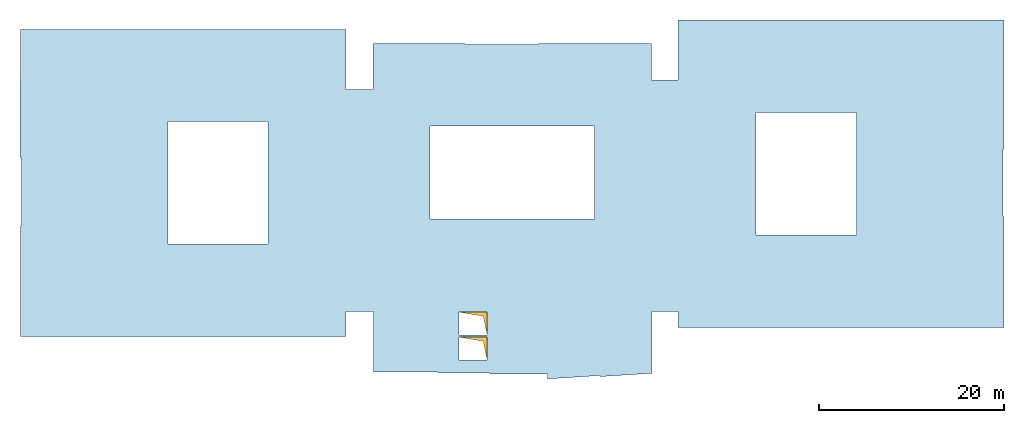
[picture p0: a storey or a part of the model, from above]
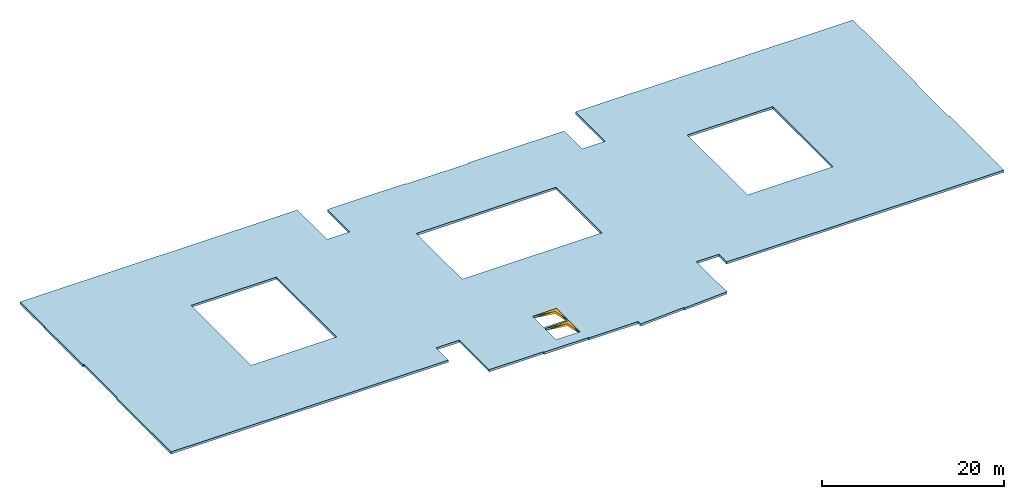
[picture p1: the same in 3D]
Properties of the parts of a building model (IFC4), part 13 of 80

# IfcCovering (3945)
Name | In | PredefinedType | Material | Allright_Bauteil_ID | Abrechnungsart | Gewerk | Schichtnummer | Schichtdicke (m) | Dicke (m) | Faktor | Objektname | AllplanAttributes, Material | Bezugshöhe | Deltahöhe | Status | D_lichte Raumhöhe [Zahl] (m)
Gipsfaserplatten 2-lagig (BSK) | WUN-H2-E01-071 | CEILING | Installationshöhe 0.764 m | 1166Dfl0000033903/02 | m² | Trockenbauarbeiten | 2 | 0.764 | 0 | 1 | Bekleidung | Installationshöhe | 0 | 0 | NEW | 2.5 | AllplanAttributes - ash_lichte Raumhöhe: 2.500000; OKFF: 0; RoomName: Einzelzimmer
Gipsfaserplatten 2-lagig (BSK) | WUN-H2-E01-071 | CEILING | A1 0.1 m | 1166Dfl0000033903/03 | m² | Trockenbauarbeiten | 3 | 0.1 | 0 | 1 | Bekleidung | A1 | 0 | 0 | NEW | 2.5 | AllplanAttributes - ash_lichte Raumhöhe: 2.500000; OKFF: 0; RoomName: Einzelzimmer; Pset_CoveringCommon - AcousticRating: -
Gipsfaserplatten 2-lagig (BSK) | WUN-H2-E01-071 | CEILING | D1 0.001 m | 1166Dfl0000033903/04 | m² | Maler- und Lackierarbeiten | 4 | 0.001 | 0 | 1 | Bekleidung | D1 | 0 | 0 | NEW | 2.5 | AllplanAttributes - ash_lichte Raumhöhe: 2.500000; OKFF: 0; RoomName: Einzelzimmer
PVC Bahnenware Holzoptik | WUN-H2-E01-071 | FLOORING | Ku1 0.15 m | 1166Bfl0000033892/01 | m² | Bodenbelagsarbeiten | 1 | 0.15 | 0 | 1 | Bodenfläche | Ku1 | 0 | 0 | NEW | AllplanAttributes - Bezeichnung: PVC Bahnenware Holzoptik; Raumnr. Bauherr: 2.11_A2_02; ash B_Aufbau: B9; ash B_Rutschhemmung: R9
Gipsfaserplatten 2-lagig (BSK) | WUN-H2-E01-071 | CEILING | layer 0.036 m | 1166Dfl0000033893/01 | m² | Trockenbauarbeiten | 1 | 0.036 | 0 | 1 | Deckenfläche |  | 0 | 0 | NEW | 3.15 | AllplanAttributes - Bezeichnung: Gipsfaserplatten 2-lagig (BSK); RoomName: Doppelzimmer
Gipsfaserplatten 2-lagig (BSK) | WUN-H2-E01-071 | CEILING | Installationshöhe 0.114 m | 1166Dfl0000033893/02 | m² | Trockenbauarbeiten | 2 | 0.114 | 0 | 1 | Bekleidung | Installationshöhe | 0 | 0 | NEW | 3.15 | AllplanAttributes - ash_lichte Raumhöhe: 3.150000; RoomName: Doppelzimmer; Pset_CoveringCommon - AcousticRating: -
Gipsfaserplatten 2-lagig (BSK) | WUN-H2-E01-071 | CEILING | A1 0.1 m | 1166Dfl0000033893/03 | m² | Trockenbauarbeiten | 3 | 0.1 | 0 | 1 | Bekleidung | A1 | 0 | 0 | NEW | 3.15 | AllplanAttributes - ash_lichte Raumhöhe: 3.150000; RoomName: Doppelzimmer; Pset_CoveringCommon - AcousticRating: -
Gipsfaserplatten 2-lagig (BSK) | WUN-H2-E01-071 | CEILING | D1 0.001 m | 1166Dfl0000033893/04 | m² | Maler- und Lackierarbeiten | 4 | 0.001 | 0 | 1 | Bekleidung | D1 | 0 | 0 | NEW | 3.15 | AllplanAttributes - ash_lichte Raumhöhe: 3.150000; RoomName: Doppelzimmer
 | WUN-H2-E01-071 | CLADDING | 49 0.001 m | 1166Sfl0000665050/01 | m² | Maler- und Lackierarbeiten | 1 | 0.001 | 0 | 1 | Seitenfläche | 49 | 150 | 3150 | NEW
Acrovyn | WUN-H2-E01-068 | CLADDING | 84 0.001 m | 1166Sfl0000220393/02 | m² | Maler- und Lackierarbeiten | 2 | 0.001 | 0 | 1 | Seitenfläche | 84 | 0 | 0 | NEW | AllplanAttributes - Bezeichnung: Acrovyn
Gipsfaserplatten 2-lagig (BSK) | WUN-H2-E01-068 | CEILING | layer 0.036 m | 1166Dfl0000033864/01 | m² | Trockenbauarbeiten | 1 | 0.036 | 0 | 1 | Deckenfläche |  | 0 | 0 | NEW | 2.5 | AllplanAttributes - Bezeichnung: Gipsfaserplatten 2-lagig (BSK); RoomName: Einzelzimmer Adipositas
Gipsfaserplatten 2-lagig (BSK) | WUN-H2-E01-068 | CEILING | Installationshöhe 0.764 m | 1166Dfl0000033864/02 | m² | Trockenbauarbeiten | 2 | 0.764 | 0 | 1 | Bekleidung | Installationshöhe | 0 | 0 | NEW | 2.5 | AllplanAttributes - ash_lichte Raumhöhe: 2.500000; OKFF: 0; RoomName: Einzelzimmer Adipositas
Gipsfaserplatten 2-lagig (BSK) | WUN-H2-E01-068 | CEILING | A1 0.1 m | 1166Dfl0000033864/03 | m² | Trockenbauarbeiten | 3 | 0.1 | 0 | 1 | Bekleidung | A1 | 0 | 0 | NEW | 2.5 | AllplanAttributes - ash_lichte Raumhöhe: 2.500000; OKFF: 0; RoomName: Einzelzimmer Adipositas; Pset_CoveringCommon - AcousticRating: -
Gipsfaserplatten 2-lagig (BSK) | WUN-H2-E01-068 | CEILING | D1 0.001 m | 1166Dfl0000033864/04 | m² | Maler- und Lackierarbeiten | 4 | 0.001 | 0 | 1 | Bekleidung | D1 | 0 | 0 | NEW | 2.5 | AllplanAttributes - ash_lichte Raumhöhe: 2.500000; OKFF: 0; RoomName: Einzelzimmer Adipositas
PVC Bahnenware Holzoptik | WUN-H2-E01-068 | FLOORING | Ku1 0.15 m | 1166Bfl0000033853/01 | m² | Bodenbelagsarbeiten | 1 | 0.15 | 0 | 1 | Bodenfläche | Ku1 | 0 | 0 | NEW | AllplanAttributes - Bezeichnung: PVC Bahnenware Holzoptik; Raumnr. Bauherr: 2.11_A2_02; ash B_Aufbau: B9; ash B_Rutschhemmung: R9
Gipsfaserplatten 2-lagig (BSK) | WUN-H2-E01-068 | CEILING | layer 0.036 m | 1166Dfl0000033854/01 | m² | Trockenbauarbeiten | 1 | 0.036 | 0 | 1 | Deckenfläche |  | 0 | 0 | NEW | 3.15 | AllplanAttributes - Bezeichnung: Gipsfaserplatten 2-lagig (BSK); RoomName: Doppelzimmer
Gipsfaserplatten 2-lagig (BSK) | WUN-H2-E01-068 | CEILING | Installationshöhe 0.114 m | 1166Dfl0000033854/02 | m² | Trockenbauarbeiten | 2 | 0.114 | 0 | 1 | Bekleidung | Installationshöhe | 0 | 0 | NEW | 3.15 | AllplanAttributes - ash_lichte Raumhöhe: 3.150000; RoomName: Doppelzimmer; Pset_CoveringCommon - AcousticRating: -
Gipsfaserplatten 2-lagig (BSK) | WUN-H2-E01-068 | CEILING | A1 0.1 m | 1166Dfl0000033854/03 | m² | Trockenbauarbeiten | 3 | 0.1 | 0 | 1 | Bekleidung | A1 | 0 | 0 | NEW | 3.15 | AllplanAttributes - ash_lichte Raumhöhe: 3.150000; RoomName: Doppelzimmer; Pset_CoveringCommon - AcousticRating: -
Gipsfaserplatten 2-lagig (BSK) | WUN-H2-E01-068 | CEILING | D1 0.001 m | 1166Dfl0000033854/04 | m² | Maler- und Lackierarbeiten | 4 | 0.001 | 0 | 1 | Bekleidung | D1 | 0 | 0 | NEW | 3.15 | AllplanAttributes - ash_lichte Raumhöhe: 3.150000; RoomName: Doppelzimmer
 | WUN-H2-E01-068 | CLADDING | 49 0.001 m | 1166Sfl0000665051/01 | m² | Maler- und Lackierarbeiten | 1 | 0.001 | 0 | 1 | Seitenfläche | 49 | 150 | 3150 | NEW
Acrovyn | WUN-H2-E01-021 | CLADDING | 84 0.001 m | 1166Sfl0000220297/02 | m² | Maler- und Lackierarbeiten | 2 | 0.001 | 0 | 1 | Seitenfläche | 84 | 0 | 0 | NEW | AllplanAttributes - Bezeichnung: Acrovyn
Acrovyn | WUN-H2-E01-021 | CLADDING | 84 0.001 m | 1166Sfl0000220331/02 | m² | Maler- und Lackierarbeiten | 2 | 0.001 | 0 | 1 | Seitenfläche | 84 | 0 | 0 | NEW | AllplanAttributes - Bezeichnung: Acrovyn
Gipsfaserplatten 2-lagig (BSK) | WUN-H2-E01-021 | CEILING | layer 0.036 m | 1166Dfl0000033322/01 | m² | Trockenbauarbeiten | 1 | 0.036 | 0 | 1 | Deckenfläche |  | 0 | 0 | NEW | 2.5 | AllplanAttributes - Bezeichnung: Gipsfaserplatten 2-lagig (BSK); RoomName: Doppelzimmer
Gipsfaserplatten 2-lagig (BSK) | WUN-H2-E01-021 | CEILING | Installationshöhe 0.764 m | 1166Dfl0000033322/02 | m² | Trockenbauarbeiten | 2 | 0.764 | 0 | 1 | Bekleidung | Installationshöhe | 0 | 0 | NEW | 2.5 | AllplanAttributes - ash_lichte Raumhöhe: 2.500000; OKFF: 0; RoomName: Doppelzimmer
Gipsfaserplatten 2-lagig (BSK) | WUN-H2-E01-021 | CEILING | A1 0.1 m | 1166Dfl0000033322/03 | m² | Trockenbauarbeiten | 3 | 0.1 | 0 | 1 | Bekleidung | A1 | 0 | 0 | NEW | 2.5 | AllplanAttributes - ash_lichte Raumhöhe: 2.500000; OKFF: 0; RoomName: Doppelzimmer; Pset_CoveringCommon - AcousticRating: -
Gipsfaserplatten 2-lagig (BSK) | WUN-H2-E01-021 | CEILING | D1 0.001 m | 1166Dfl0000033322/04 | m² | Maler- und Lackierarbeiten | 4 | 0.001 | 0 | 1 | Bekleidung | D1 | 0 | 0 | NEW | 2.5 | AllplanAttributes - ash_lichte Raumhöhe: 2.500000; OKFF: 0; RoomName: Doppelzimmer
PVC Bahnenware Holzoptik | WUN-H2-E01-021 | FLOORING | Ku1 0.15 m | 1166Bfl0000033311/01 | m² | Bodenbelagsarbeiten | 1 | 0.15 | 0 | 1 | Bodenfläche | Ku1 | 0 | 0 | NEW | AllplanAttributes - Bezeichnung: PVC Bahnenware Holzoptik; Raumnr. Bauherr: 2.11_A2_02; ash B_Aufbau: B9; ash B_Rutschhemmung: R9
Gipsfaserplatten 2-lagig (BSK) | WUN-H2-E01-021 | CEILING | layer 0.036 m | 1166Dfl0000033312/01 | m² | Trockenbauarbeiten | 1 | 0.036 | 0 | 1 | Deckenfläche |  | 0 | 0 | NEW | 3.15 | AllplanAttributes - Bezeichnung: Gipsfaserplatten 2-lagig (BSK); RoomName: Doppelzimmer
Gipsfaserplatten 2-lagig (BSK) | WUN-H2-E01-021 | CEILING | Installationshöhe 0.114 m | 1166Dfl0000033312/02 | m² | Trockenbauarbeiten | 2 | 0.114 | 0 | 1 | Bekleidung | Installationshöhe | 0 | 0 | NEW | 3.15 | AllplanAttributes - ash_lichte Raumhöhe: 3.150000; RoomName: Doppelzimmer; Pset_CoveringCommon - AcousticRating: -
Gipsfaserplatten 2-lagig (BSK) | WUN-H2-E01-021 | CEILING | A1 0.1 m | 1166Dfl0000033312/03 | m² | Trockenbauarbeiten | 3 | 0.1 | 0 | 1 | Bekleidung | A1 | 0 | 0 | NEW | 3.15 | AllplanAttributes - ash_lichte Raumhöhe: 3.150000; RoomName: Doppelzimmer; Pset_CoveringCommon - AcousticRating: -
Gipsfaserplatten 2-lagig (BSK) | WUN-H2-E01-021 | CEILING | D1 0.001 m | 1166Dfl0000033312/04 | m² | Maler- und Lackierarbeiten | 4 | 0.001 | 0 | 1 | Bekleidung | D1 | 0 | 0 | NEW | 3.15 | AllplanAttributes - ash_lichte Raumhöhe: 3.150000; RoomName: Doppelzimmer
 | WUN-H2-E01-021 | CLADDING | 49 0.001 m | 1166Sfl0000665052/01 | m² | Maler- und Lackierarbeiten | 1 | 0.001 | 0 | 1 | Seitenfläche | 49 | 150 | 3150 | NEW
Acrovyn | WUN-H2-E01-022 | CLADDING | 84 0.001 m | 1166Sfl0000220295/02 | m² | Maler- und Lackierarbeiten | 2 | 0.001 | 0 | 1 | Seitenfläche | 84 | 0 | 0 | NEW | AllplanAttributes - Bezeichnung: Acrovyn
Gipsfaserplatten 2-lagig (BSK) | WUN-H2-E01-022 | CEILING | layer 0.036 m | 1166Dfl0000033335/01 | m² | Trockenbauarbeiten | 1 | 0.036 | 0 | 1 | Deckenfläche |  | 0 | 0 | NEW | 2.5 | AllplanAttributes - Bezeichnung: Gipsfaserplatten 2-lagig (BSK); RoomName: Einzelzimmer
Gipsfaserplatten 2-lagig (BSK) | WUN-H2-E01-022 | CEILING | Installationshöhe 0.764 m | 1166Dfl0000033335/02 | m² | Trockenbauarbeiten | 2 | 0.764 | 0 | 1 | Bekleidung | Installationshöhe | 0 | 0 | NEW | 2.5 | AllplanAttributes - ash_lichte Raumhöhe: 2.500000; OKFF: 0; RoomName: Einzelzimmer
Gipsfaserplatten 2-lagig (BSK) | WUN-H2-E01-022 | CEILING | A1 0.1 m | 1166Dfl0000033335/03 | m² | Trockenbauarbeiten | 3 | 0.1 | 0 | 1 | Bekleidung | A1 | 0 | 0 | NEW | 2.5 | AllplanAttributes - ash_lichte Raumhöhe: 2.500000; OKFF: 0; RoomName: Einzelzimmer; Pset_CoveringCommon - AcousticRating: -
Gipsfaserplatten 2-lagig (BSK) | WUN-H2-E01-022 | CEILING | D1 0.001 m | 1166Dfl0000033335/04 | m² | Maler- und Lackierarbeiten | 4 | 0.001 | 0 | 1 | Bekleidung | D1 | 0 | 0 | NEW | 2.5 | AllplanAttributes - ash_lichte Raumhöhe: 2.500000; OKFF: 0; RoomName: Einzelzimmer
PVC Bahnenware Holzoptik | WUN-H2-E01-022 | FLOORING | Ku1 0.15 m | 1166Bfl0000033324/01 | m² | Bodenbelagsarbeiten | 1 | 0.15 | 0 | 1 | Bodenfläche | Ku1 | 0 | 0 | NEW | AllplanAttributes - Bezeichnung: PVC Bahnenware Holzoptik; Raumnr. Bauherr: 2.11_A2_02; ash B_Aufbau: B9; ash B_Rutschhemmung: R9
Gipsfaserplatten 2-lagig (BSK) | WUN-H2-E01-022 | CEILING | layer 0.036 m | 1166Dfl0000033325/01 | m² | Trockenbauarbeiten | 1 | 0.036 | 0 | 1 | Deckenfläche |  | 0 | 0 | NEW | 3.15 | AllplanAttributes - Bezeichnung: Gipsfaserplatten 2-lagig (BSK); RoomName: Doppelzimmer
Gipsfaserplatten 2-lagig (BSK) | WUN-H2-E01-022 | CEILING | Installationshöhe 0.114 m | 1166Dfl0000033325/02 | m² | Trockenbauarbeiten | 2 | 0.114 | 0 | 1 | Bekleidung | Installationshöhe | 0 | 0 | NEW | 3.15 | AllplanAttributes - ash_lichte Raumhöhe: 3.150000; RoomName: Doppelzimmer; Pset_CoveringCommon - AcousticRating: -
Gipsfaserplatten 2-lagig (BSK) | WUN-H2-E01-022 | CEILING | A1 0.1 m | 1166Dfl0000033325/03 | m² | Trockenbauarbeiten | 3 | 0.1 | 0 | 1 | Bekleidung | A1 | 0 | 0 | NEW | 3.15 | AllplanAttributes - ash_lichte Raumhöhe: 3.150000; RoomName: Doppelzimmer; Pset_CoveringCommon - AcousticRating: -
Gipsfaserplatten 2-lagig (BSK) | WUN-H2-E01-022 | CEILING | D1 0.001 m | 1166Dfl0000033325/04 | m² | Maler- und Lackierarbeiten | 4 | 0.001 | 0 | 1 | Bekleidung | D1 | 0 | 0 | NEW | 3.15 | AllplanAttributes - ash_lichte Raumhöhe: 3.150000; RoomName: Doppelzimmer
 | WUN-H2-E01-022 | CLADDING | 49 0.001 m | 1166Sfl0000665053/01 | m² | Maler- und Lackierarbeiten | 1 | 0.001 | 0 | 1 | Seitenfläche | 49 | 150 | 3150 | NEW
Acrovyn | WUN-H2-E01-023 | CLADDING | 84 0.001 m | 1166Sfl0000220293/02 | m² | Maler- und Lackierarbeiten | 2 | 0.001 | 0 | 1 | Seitenfläche | 84 | 0 | 0 | NEW | AllplanAttributes - Bezeichnung: Acrovyn
Acrovyn | WUN-H2-E01-023 | CLADDING | 84 0.001 m | 1166Sfl0000220333/02 | m² | Maler- und Lackierarbeiten | 2 | 0.001 | 0 | 1 | Seitenfläche | 84 | 0 | 0 | NEW | AllplanAttributes - Bezeichnung: Acrovyn
Gipsfaserplatten 2-lagig (BSK) | WUN-H2-E01-023 | CEILING | layer 0.036 m | 1166Dfl0000033348/01 | m² | Trockenbauarbeiten | 1 | 0.036 | 0 | 1 | Deckenfläche |  | 0 | 0 | NEW | 2.5 | AllplanAttributes - Bezeichnung: Gipsfaserplatten 2-lagig (BSK); RoomName: Rollstuhlgerechtes Doppelzimmer
Gipsfaserplatten 2-lagig (BSK) | WUN-H2-E01-023 | CEILING | Installationshöhe 0.764 m | 1166Dfl0000033348/02 | m² | Trockenbauarbeiten | 2 | 0.764 | 0 | 1 | Bekleidung | Installationshöhe | 0 | 0 | NEW | 2.5 | AllplanAttributes - ash_lichte Raumhöhe: 2.500000; OKFF: 0; RoomName: Rollstuhlgerechtes Doppelzimmer
Gipsfaserplatten 2-lagig (BSK) | WUN-H2-E01-023 | CEILING | A1 0.1 m | 1166Dfl0000033348/03 | m² | Trockenbauarbeiten | 3 | 0.1 | 0 | 1 | Bekleidung | A1 | 0 | 0 | NEW | 2.5 | AllplanAttributes - ash_lichte Raumhöhe: 2.500000; OKFF: 0; RoomName: Rollstuhlgerechtes Doppelzimmer; Pset_CoveringCommon - AcousticRating: -
Gipsfaserplatten 2-lagig (BSK) | WUN-H2-E01-023 | CEILING | D1 0.001 m | 1166Dfl0000033348/04 | m² | Maler- und Lackierarbeiten | 4 | 0.001 | 0 | 1 | Bekleidung | D1 | 0 | 0 | NEW | 2.5 | AllplanAttributes - ash_lichte Raumhöhe: 2.500000; OKFF: 0; RoomName: Rollstuhlgerechtes Doppelzimmer
PVC Bahnenware Holzoptik | WUN-H2-E01-023 | FLOORING | Ku1 0.15 m | 1166Bfl0000033337/01 | m² | Bodenbelagsarbeiten | 1 | 0.15 | 0 | 1 | Bodenfläche | Ku1 | 0 | 0 | NEW | AllplanAttributes - Bezeichnung: PVC Bahnenware Holzoptik; Raumnr. Bauherr: 2.11_A2_02; ash B_Aufbau: B9; ash B_Rutschhemmung: R9
Gipsfaserplatten 2-lagig (BSK) | WUN-H2-E01-023 | CEILING | layer 0.036 m | 1166Dfl0000033338/01 | m² | Trockenbauarbeiten | 1 | 0.036 | 0 | 1 | Deckenfläche |  | 0 | 0 | NEW | 3.15 | AllplanAttributes - Bezeichnung: Gipsfaserplatten 2-lagig (BSK); RoomName: Doppelzimmer
Gipsfaserplatten 2-lagig (BSK) | WUN-H2-E01-023 | CEILING | Installationshöhe 0.114 m | 1166Dfl0000033338/02 | m² | Trockenbauarbeiten | 2 | 0.114 | 0 | 1 | Bekleidung | Installationshöhe | 0 | 0 | NEW | 3.15 | AllplanAttributes - ash_lichte Raumhöhe: 3.150000; RoomName: Doppelzimmer; Pset_CoveringCommon - AcousticRating: -
Gipsfaserplatten 2-lagig (BSK) | WUN-H2-E01-023 | CEILING | A1 0.1 m | 1166Dfl0000033338/03 | m² | Trockenbauarbeiten | 3 | 0.1 | 0 | 1 | Bekleidung | A1 | 0 | 0 | NEW | 3.15 | AllplanAttributes - ash_lichte Raumhöhe: 3.150000; RoomName: Doppelzimmer; Pset_CoveringCommon - AcousticRating: -
Gipsfaserplatten 2-lagig (BSK) | WUN-H2-E01-023 | CEILING | D1 0.001 m | 1166Dfl0000033338/04 | m² | Maler- und Lackierarbeiten | 4 | 0.001 | 0 | 1 | Bekleidung | D1 | 0 | 0 | NEW | 3.15 | AllplanAttributes - ash_lichte Raumhöhe: 3.150000; RoomName: Doppelzimmer
 | WUN-H2-E01-023 | CLADDING | 49 0.001 m | 1166Sfl0000665054/01 | m² | Maler- und Lackierarbeiten | 1 | 0.001 | 0 | 1 | Seitenfläche | 49 | 150 | 3150 | NEW
Acrovyn | WUN-H2-E01-024 | CLADDING | 84 0.001 m | 1166Sfl0000220291/02 | m² | Maler- und Lackierarbeiten | 2 | 0.001 | 0 | 1 | Seitenfläche | 84 | 0 | 0 | NEW | AllplanAttributes - Bezeichnung: Acrovyn
Acrovyn | WUN-H2-E01-024 | CLADDING | 84 0.001 m | 1166Sfl0000220335/02 | m² | Maler- und Lackierarbeiten | 2 | 0.001 | 0 | 1 | Seitenfläche | 84 | 0 | 0 | NEW | AllplanAttributes - Bezeichnung: Acrovyn
Gipsfaserplatten 2-lagig (BSK) | WUN-H2-E01-024 | CEILING | layer 0.036 m | 1166Dfl0000033361/01 | m² | Trockenbauarbeiten | 1 | 0.036 | 0 | 1 | Deckenfläche |  | 0 | 0 | NEW | 2.5 | AllplanAttributes - Bezeichnung: Gipsfaserplatten 2-lagig (BSK); RoomName: Doppelzimmer
Gipsfaserplatten 2-lagig (BSK) | WUN-H2-E01-024 | CEILING | Installationshöhe 0.764 m | 1166Dfl0000033361/02 | m² | Trockenbauarbeiten | 2 | 0.764 | 0 | 1 | Bekleidung | Installationshöhe | 0 | 0 | NEW | 2.5 | AllplanAttributes - ash_lichte Raumhöhe: 2.500000; OKFF: 0; RoomName: Doppelzimmer
Gipsfaserplatten 2-lagig (BSK) | WUN-H2-E01-024 | CEILING | A1 0.1 m | 1166Dfl0000033361/03 | m² | Trockenbauarbeiten | 3 | 0.1 | 0 | 1 | Bekleidung | A1 | 0 | 0 | NEW | 2.5 | AllplanAttributes - ash_lichte Raumhöhe: 2.500000; OKFF: 0; RoomName: Doppelzimmer; Pset_CoveringCommon - AcousticRating: -
Gipsfaserplatten 2-lagig (BSK) | WUN-H2-E01-024 | CEILING | D1 0.001 m | 1166Dfl0000033361/04 | m² | Maler- und Lackierarbeiten | 4 | 0.001 | 0 | 1 | Bekleidung | D1 | 0 | 0 | NEW | 2.5 | AllplanAttributes - ash_lichte Raumhöhe: 2.500000; OKFF: 0; RoomName: Doppelzimmer
PVC Bahnenware Holzoptik | WUN-H2-E01-024 | FLOORING | Ku1 0.15 m | 1166Bfl0000033350/01 | m² | Bodenbelagsarbeiten | 1 | 0.15 | 0 | 1 | Bodenfläche | Ku1 | 0 | 0 | NEW | AllplanAttributes - Bezeichnung: PVC Bahnenware Holzoptik; Raumnr. Bauherr: 2.11_A2_02; ash B_Aufbau: B9; ash B_Rutschhemmung: R9
Gipsfaserplatten 2-lagig (BSK) | WUN-H2-E01-024 | CEILING | layer 0.036 m | 1166Dfl0000033351/01 | m² | Trockenbauarbeiten | 1 | 0.036 | 0 | 1 | Deckenfläche |  | 0 | 0 | NEW | 3.15 | AllplanAttributes - Bezeichnung: Gipsfaserplatten 2-lagig (BSK); RoomName: Doppelzimmer
Gipsfaserplatten 2-lagig (BSK) | WUN-H2-E01-024 | CEILING | Installationshöhe 0.114 m | 1166Dfl0000033351/02 | m² | Trockenbauarbeiten | 2 | 0.114 | 0 | 1 | Bekleidung | Installationshöhe | 0 | 0 | NEW | 3.15 | AllplanAttributes - ash_lichte Raumhöhe: 3.150000; RoomName: Doppelzimmer; Pset_CoveringCommon - AcousticRating: -
Gipsfaserplatten 2-lagig (BSK) | WUN-H2-E01-024 | CEILING | A1 0.1 m | 1166Dfl0000033351/03 | m² | Trockenbauarbeiten | 3 | 0.1 | 0 | 1 | Bekleidung | A1 | 0 | 0 | NEW | 3.15 | AllplanAttributes - ash_lichte Raumhöhe: 3.150000; RoomName: Doppelzimmer; Pset_CoveringCommon - AcousticRating: -
Gipsfaserplatten 2-lagig (BSK) | WUN-H2-E01-024 | CEILING | D1 0.001 m | 1166Dfl0000033351/04 | m² | Maler- und Lackierarbeiten | 4 | 0.001 | 0 | 1 | Bekleidung | D1 | 0 | 0 | NEW | 3.15 | AllplanAttributes - ash_lichte Raumhöhe: 3.150000; RoomName: Doppelzimmer
 | WUN-H2-E01-024 | CLADDING | 49 0.001 m | 1166Sfl0000665055/01 | m² | Maler- und Lackierarbeiten | 1 | 0.001 | 0 | 1 | Seitenfläche | 49 | 150 | 3150 | NEW
Acrovyn | WUN-H2-E01-025 | CLADDING | 84 0.001 m | 1166Sfl0000220000/02 | m² | Maler- und Lackierarbeiten | 2 | 0.001 | 0 | 1 | Seitenfläche | 84 | 0 | 0 | NEW | AllplanAttributes - Bezeichnung: Acrovyn
Acrovyn | WUN-H2-E01-025 | CLADDING | 84 0.001 m | 1166Sfl0000220337/02 | m² | Maler- und Lackierarbeiten | 2 | 0.001 | 0 | 1 | Seitenfläche | 84 | 0 | 0 | NEW | AllplanAttributes - Bezeichnung: Acrovyn
Gipsfaserplatten 2-lagig (BSK) | WUN-H2-E01-025 | CEILING | layer 0.036 m | 1166Dfl0000033374/01 | m² | Trockenbauarbeiten | 1 | 0.036 | 0 | 1 | Deckenfläche |  | 0 | 0 | NEW | 2.5 | AllplanAttributes - Bezeichnung: Gipsfaserplatten 2-lagig (BSK); RoomName: Doppelzimmer
Gipsfaserplatten 2-lagig (BSK) | WUN-H2-E01-025 | CEILING | Installationshöhe 0.764 m | 1166Dfl0000033374/02 | m² | Trockenbauarbeiten | 2 | 0.764 | 0 | 1 | Bekleidung | Installationshöhe | 0 | 0 | NEW | 2.5 | AllplanAttributes - ash_lichte Raumhöhe: 2.500000; OKFF: 0; RoomName: Doppelzimmer
Gipsfaserplatten 2-lagig (BSK) | WUN-H2-E01-025 | CEILING | A1 0.1 m | 1166Dfl0000033374/03 | m² | Trockenbauarbeiten | 3 | 0.1 | 0 | 1 | Bekleidung | A1 | 0 | 0 | NEW | 2.5 | AllplanAttributes - ash_lichte Raumhöhe: 2.500000; OKFF: 0; RoomName: Doppelzimmer; Pset_CoveringCommon - AcousticRating: -
Gipsfaserplatten 2-lagig (BSK) | WUN-H2-E01-025 | CEILING | D1 0.001 m | 1166Dfl0000033374/04 | m² | Maler- und Lackierarbeiten | 4 | 0.001 | 0 | 1 | Bekleidung | D1 | 0 | 0 | NEW | 2.5 | AllplanAttributes - ash_lichte Raumhöhe: 2.500000; OKFF: 0; RoomName: Doppelzimmer
PVC Bahnenware Holzoptik | WUN-H2-E01-025 | FLOORING | Ku1 0.15 m | 1166Bfl0000033363/01 | m² | Bodenbelagsarbeiten | 1 | 0.15 | 0 | 1 | Bodenfläche | Ku1 | 0 | 0 | NEW | AllplanAttributes - Bezeichnung: PVC Bahnenware Holzoptik; Raumnr. Bauherr: 2.11_A2_02; ash B_Aufbau: B9; ash B_Rutschhemmung: R9
Gipsfaserplatten 2-lagig (BSK) | WUN-H2-E01-025 | CEILING | layer 0.036 m | 1166Dfl0000033364/01 | m² | Trockenbauarbeiten | 1 | 0.036 | 0 | 1 | Deckenfläche |  | 0 | 0 | NEW | 3.15 | AllplanAttributes - Bezeichnung: Gipsfaserplatten 2-lagig (BSK); RoomName: Doppelzimmer
Gipsfaserplatten 2-lagig (BSK) | WUN-H2-E01-025 | CEILING | Installationshöhe 0.114 m | 1166Dfl0000033364/02 | m² | Trockenbauarbeiten | 2 | 0.114 | 0 | 1 | Bekleidung | Installationshöhe | 0 | 0 | NEW | 3.15 | AllplanAttributes - ash_lichte Raumhöhe: 3.150000; RoomName: Doppelzimmer; Pset_CoveringCommon - AcousticRating: -
Gipsfaserplatten 2-lagig (BSK) | WUN-H2-E01-025 | CEILING | A1 0.1 m | 1166Dfl0000033364/03 | m² | Trockenbauarbeiten | 3 | 0.1 | 0 | 1 | Bekleidung | A1 | 0 | 0 | NEW | 3.15 | AllplanAttributes - ash_lichte Raumhöhe: 3.150000; RoomName: Doppelzimmer; Pset_CoveringCommon - AcousticRating: -
Gipsfaserplatten 2-lagig (BSK) | WUN-H2-E01-025 | CEILING | D1 0.001 m | 1166Dfl0000033364/04 | m² | Maler- und Lackierarbeiten | 4 | 0.001 | 0 | 1 | Bekleidung | D1 | 0 | 0 | NEW | 3.15 | AllplanAttributes - ash_lichte Raumhöhe: 3.150000; RoomName: Doppelzimmer
 | WUN-H2-E01-025 | CLADDING | 49 0.001 m | 1166Sfl0000665056/01 | m² | Maler- und Lackierarbeiten | 1 | 0.001 | 0 | 1 | Seitenfläche | 49 | 150 | 3150 | NEW
Fliesen Mosaik | WUN-H2-E01-090a | FLOORING | Fl2 0.15 m | 1166Bfl0000492017/01 | m² | Bodenbelagsarbeiten | 1 | 0.15 | 0 | 1 | Bodenfläche | Fl2 | 0 | 0 | NEW | AllplanAttributes - Bezeichnung: Fliesen Mosaik; Raumnr. Bauherr: 2.11_A2_02; ash B_Aufbau: B11; ash B_Rutschhemmung: R10; ash B_Bewertungsgruppe Barfußbereich: B
Fliesen | WUN-H2-E01-090a | FLOORING | Fl1 0.15 m | 1166Bfl0000034444/01 | m² | Bodenbelagsarbeiten | 1 | 0.15 | 0 | 1 | Bodenfläche | Fl1 | 0 | 0 | NEW | AllplanAttributes - Bezeichnung: Fliesen; Raumnr. Bauherr: 2.11_A2_02; ash B_Aufbau: B10; ash B_Rutschhemmung: R10
Gipsfaserplatten 2-lagig (BSK) | WUN-H2-E01-090a | CEILING | layer 0.036 m | 1166Dfl0000034445/01 | m² | Trockenbauarbeiten | 1 | 0.036 | 0 | 1 | Deckenfläche |  | 0 | 0 | NEW | 2.5 | AllplanAttributes - Bezeichnung: Gipsfaserplatten 2-lagig (BSK); RoomName: Nasszelle DZ
Gipsfaserplatten 2-lagig (BSK) | WUN-H2-E01-090a | CEILING | Installationshöhe 0.764 m | 1166Dfl0000034445/02 | m² | Trockenbauarbeiten | 2 | 0.764 | 0 | 1 | Bekleidung | Installationshöhe | 0 | 0 | NEW | 2.5 | AllplanAttributes - ash_lichte Raumhöhe: 2.500000; OKFF: 0; RoomName: Nasszelle DZ
Gipskarton, imprägniert | WUN-H2-E01-090a | CEILING | B 0.1 m | 1166Dfl0000034445/03 | m² | Trockenbauarbeiten | 3 | 0.1 | 0 | 1 | Bekleidung | B | 0 | 0 | NEW | 2.5 | AllplanAttributes - Bezeichnung: Gipskarton, imprägniert; ash_lichte Raumhöhe: 2.500000; OKFF: 0; RoomName: Nasszelle DZ; Pset_CoveringCommon - AcousticRating: -
Gipsfaserplatten 2-lagig (BSK) | WUN-H2-E01-090a | CEILING | D1 0.001 m | 1166Dfl0000034445/04 | m² | Maler- und Lackierarbeiten | 4 | 0.001 | 0 | 1 | Bekleidung | D1 | 0 | 0 | NEW | 2.5 | AllplanAttributes - ash_lichte Raumhöhe: 2.500000; OKFF: 0; RoomName: Nasszelle DZ
 | WUN-H2-E01-090a | CLADDING | 50 0.001 m | 1166Sfl0000665057/01 | m² | Maler- und Lackierarbeiten | 1 | 0.001 | 0 | 1 | Seitenfläche | 50 | 150 | 2500 | NEW
a-sh Wandbelag | WUN-H2-E01-090a | CLADDING | 68 0.01 m | 1166Sfl0000666811/01 | m² | Maler- und Lackierarbeiten | 1 | 0.01 | 0 | 1 | Seitenfläche | 68 | 100 | 3000 | NEW | AllplanAttributes - Bezeichnung: a-sh Wandbelag; Attributset-Objekt: Covering
Fliesen Mosaik | WUN-H2-E01-069a | FLOORING | Fl2 0.15 m | 1166Bfl0000493217/01 | m² | Bodenbelagsarbeiten | 1 | 0.15 | 0 | 1 | Bodenfläche | Fl2 | 0 | 0 | NEW | AllplanAttributes - Bezeichnung: Fliesen Mosaik; Raumnr. Bauherr: 2.11_A2_02; ash B_Aufbau: B11; ash B_Rutschhemmung: R10; ash B_Bewertungsgruppe Barfußbereich: B
Fliesen | WUN-H2-E01-069a | FLOORING | Fl1 0.15 m | 1166Bfl0000033955/01 | m² | Bodenbelagsarbeiten | 1 | 0.15 | 0 | 1 | Bodenfläche | Fl1 | 0 | 0 | NEW | AllplanAttributes - Bezeichnung: Fliesen; Raumnr. Bauherr: 2.11_A2_02; ash B_Aufbau: B10; ash B_Rutschhemmung: R10
Gipsfaserplatten 2-lagig (BSK) | WUN-H2-E01-069a | CEILING | layer 0.036 m | 1166Dfl0000033956/01 | m² | Trockenbauarbeiten | 1 | 0.036 | 0 | 1 | Deckenfläche |  | 0 | 0 | NEW | 2.5 | AllplanAttributes - Bezeichnung: Gipsfaserplatten 2-lagig (BSK); RoomName: Nasszelle DZ
Gipsfaserplatten 2-lagig (BSK) | WUN-H2-E01-069a | CEILING | Installationshöhe 0.764 m | 1166Dfl0000033956/02 | m² | Trockenbauarbeiten | 2 | 0.764 | 0 | 1 | Bekleidung | Installationshöhe | 0 | 0 | NEW | 2.5 | AllplanAttributes - ash_lichte Raumhöhe: 2.500000; OKFF: 0; RoomName: Nasszelle DZ
Gipskarton, imprägniert | WUN-H2-E01-069a | CEILING | B 0.1 m | 1166Dfl0000033956/03 | m² | Trockenbauarbeiten | 3 | 0.1 | 0 | 1 | Bekleidung | B | 0 | 0 | NEW | 2.5 | AllplanAttributes - Bezeichnung: Gipskarton, imprägniert; ash_lichte Raumhöhe: 2.500000; OKFF: 0; RoomName: Nasszelle DZ; Pset_CoveringCommon - AcousticRating: -
Gipsfaserplatten 2-lagig (BSK) | WUN-H2-E01-069a | CEILING | D1 0.001 m | 1166Dfl0000033956/04 | m² | Maler- und Lackierarbeiten | 4 | 0.001 | 0 | 1 | Bekleidung | D1 | 0 | 0 | NEW | 2.5 | AllplanAttributes - ash_lichte Raumhöhe: 2.500000; OKFF: 0; RoomName: Nasszelle DZ
 | WUN-H2-E01-069a | CLADDING | 50 0.001 m | 1166Sfl0000665058/01 | m² | Maler- und Lackierarbeiten | 1 | 0.001 | 0 | 1 | Seitenfläche | 50 | 150 | 2500 | NEW
a-sh Wandbelag | WUN-H2-E01-069a | CLADDING | 68 0.01 m | 1166Sfl0000666890/01 | m² | Maler- und Lackierarbeiten | 1 | 0.01 | 0 | 1 | Seitenfläche | 68 | 100 | 3000 | NEW | AllplanAttributes - Bezeichnung: a-sh Wandbelag; Attributset-Objekt: Covering
Fliesen Mosaik | WUN-H2-E01-070a | FLOORING | Fl2 0.15 m | 1166Bfl0000493017/01 | m² | Bodenbelagsarbeiten | 1 | 0.15 | 0 | 1 | Bodenfläche | Fl2 | 0 | 0 | NEW | AllplanAttributes - Bezeichnung: Fliesen Mosaik; Raumnr. Bauherr: 2.11_A2_02; ash B_Aufbau: B11; ash B_Rutschhemmung: R10; ash B_Bewertungsgruppe Barfußbereich: B
Fliesen | WUN-H2-E01-070a | FLOORING | Fl1 0.15 m | 1166Bfl0000033966/01 | m² | Bodenbelagsarbeiten | 1 | 0.15 | 0 | 1 | Bodenfläche | Fl1 | 0 | 0 | NEW | AllplanAttributes - Bezeichnung: Fliesen; Raumnr. Bauherr: 2.11_A2_02; ash B_Aufbau: B10; ash B_Rutschhemmung: R10
Gipsfaserplatten 2-lagig (BSK) | WUN-H2-E01-070a | CEILING | layer 0.036 m | 1166Dfl0000033967/01 | m² | Trockenbauarbeiten | 1 | 0.036 | 0 | 1 | Deckenfläche |  | 0 | 0 | NEW | 2.5 | AllplanAttributes - Bezeichnung: Gipsfaserplatten 2-lagig (BSK); RoomName: Nasszelle DZ
Gipsfaserplatten 2-lagig (BSK) | WUN-H2-E01-070a | CEILING | Installationshöhe 0.764 m | 1166Dfl0000033967/02 | m² | Trockenbauarbeiten | 2 | 0.764 | 0 | 1 | Bekleidung | Installationshöhe | 0 | 0 | NEW | 2.5 | AllplanAttributes - ash_lichte Raumhöhe: 2.500000; OKFF: 0; RoomName: Nasszelle DZ
Gipskarton, imprägniert | WUN-H2-E01-070a | CEILING | B 0.1 m | 1166Dfl0000033967/03 | m² | Trockenbauarbeiten | 3 | 0.1 | 0 | 1 | Bekleidung | B | 0 | 0 | NEW | 2.5 | AllplanAttributes - Bezeichnung: Gipskarton, imprägniert; ash_lichte Raumhöhe: 2.500000; OKFF: 0; RoomName: Nasszelle DZ; Pset_CoveringCommon - AcousticRating: -
Gipsfaserplatten 2-lagig (BSK) | WUN-H2-E01-070a | CEILING | D1 0.001 m | 1166Dfl0000033967/04 | m² | Maler- und Lackierarbeiten | 4 | 0.001 | 0 | 1 | Bekleidung | D1 | 0 | 0 | NEW | 2.5 | AllplanAttributes - ash_lichte Raumhöhe: 2.500000; OKFF: 0; RoomName: Nasszelle DZ
 | WUN-H2-E01-070a | CLADDING | 50 0.001 m | 1166Sfl0000665059/01 | m² | Maler- und Lackierarbeiten | 1 | 0.001 | 0 | 1 | Seitenfläche | 50 | 150 | 2500 | NEW
a-sh Wandbelag | WUN-H2-E01-070a | CLADDING | 68 0.01 m | 1166Sfl0000666959/01 | m² | Maler- und Lackierarbeiten | 1 | 0.01 | 0 | 1 | Seitenfläche | 68 | 100 | 3000 | NEW | AllplanAttributes - Bezeichnung: a-sh Wandbelag; Attributset-Objekt: Covering
Fliesen Mosaik | WUN-H2-E01-071a | FLOORING | Fl2 0.15 m | 1166Bfl0000492817/01 | m² | Bodenbelagsarbeiten | 1 | 0.15 | 0 | 1 | Bodenfläche | Fl2 | 0 | 0 | NEW | AllplanAttributes - Bezeichnung: Fliesen Mosaik; Raumnr. Bauherr: 2.11_A2_02; ash B_Aufbau: B11; ash B_Rutschhemmung: R10; ash B_Bewertungsgruppe Barfußbereich: B
Fliesen | WUN-H2-E01-071a | FLOORING | Fl1 0.15 m | 1166Bfl0000033977/01 | m² | Bodenbelagsarbeiten | 1 | 0.15 | 0 | 1 | Bodenfläche | Fl1 | 0 | 0 | NEW | AllplanAttributes - Bezeichnung: Fliesen; Raumnr. Bauherr: 2.11_A2_02; ash B_Aufbau: B10; ash B_Rutschhemmung: R10
Gipsfaserplatten 2-lagig (BSK) | WUN-H2-E01-071a | CEILING | layer 0.036 m | 1166Dfl0000033978/01 | m² | Trockenbauarbeiten | 1 | 0.036 | 0 | 1 | Deckenfläche |  | 0 | 0 | NEW | 2.5 | AllplanAttributes - Bezeichnung: Gipsfaserplatten 2-lagig (BSK); RoomName: Nasszelle DZ
Gipsfaserplatten 2-lagig (BSK) | WUN-H2-E01-071a | CEILING | Installationshöhe 0.764 m | 1166Dfl0000033978/02 | m² | Trockenbauarbeiten | 2 | 0.764 | 0 | 1 | Bekleidung | Installationshöhe | 0 | 0 | NEW | 2.5 | AllplanAttributes - ash_lichte Raumhöhe: 2.500000; OKFF: 0; RoomName: Nasszelle DZ
Gipskarton, imprägniert | WUN-H2-E01-071a | CEILING | B 0.1 m | 1166Dfl0000033978/03 | m² | Trockenbauarbeiten | 3 | 0.1 | 0 | 1 | Bekleidung | B | 0 | 0 | NEW | 2.5 | AllplanAttributes - Bezeichnung: Gipskarton, imprägniert; ash_lichte Raumhöhe: 2.500000; OKFF: 0; RoomName: Nasszelle DZ; Pset_CoveringCommon - AcousticRating: -
Gipsfaserplatten 2-lagig (BSK) | WUN-H2-E01-071a | CEILING | D1 0.001 m | 1166Dfl0000033978/04 | m² | Maler- und Lackierarbeiten | 4 | 0.001 | 0 | 1 | Bekleidung | D1 | 0 | 0 | NEW | 2.5 | AllplanAttributes - ash_lichte Raumhöhe: 2.500000; OKFF: 0; RoomName: Nasszelle DZ
 | WUN-H2-E01-071a | CLADDING | 50 0.001 m | 1166Sfl0000665060/01 | m² | Maler- und Lackierarbeiten | 1 | 0.001 | 0 | 1 | Seitenfläche | 50 | 150 | 2500 | NEW
a-sh Wandbelag | WUN-H2-E01-071a | CLADDING | 68 0.01 m | 1166Sfl0000667304/01 | m² | Maler- und Lackierarbeiten | 1 | 0.01 | 0 | 1 | Seitenfläche | 68 | 100 | 3000 | NEW | AllplanAttributes - Bezeichnung: a-sh Wandbelag; Attributset-Objekt: Covering
Fliesen Mosaik | WUN-H2-E01-072a | FLOORING | Fl2 0.15 m | 1166Bfl0000492617/01 | m² | Bodenbelagsarbeiten | 1 | 0.15 | 0 | 1 | Bodenfläche | Fl2 | 0 | 0 | NEW | AllplanAttributes - Bezeichnung: Fliesen Mosaik; Raumnr. Bauherr: 2.11_A2_02; ash B_Aufbau: B11; ash B_Rutschhemmung: R10; ash B_Bewertungsgruppe Barfußbereich: B
Fliesen | WUN-H2-E01-072a | FLOORING | Fl1 0.15 m | 1166Bfl0000033988/01 | m² | Bodenbelagsarbeiten | 1 | 0.15 | 0 | 1 | Bodenfläche | Fl1 | 0 | 0 | NEW | AllplanAttributes - Bezeichnung: Fliesen; Raumnr. Bauherr: 2.11_A2_02; ash B_Aufbau: B10; ash B_Rutschhemmung: R10
Gipsfaserplatten 2-lagig (BSK) | WUN-H2-E01-072a | CEILING | layer 0.036 m | 1166Dfl0000033989/01 | m² | Trockenbauarbeiten | 1 | 0.036 | 0 | 1 | Deckenfläche |  | 0 | 0 | NEW | 2.5 | AllplanAttributes - Bezeichnung: Gipsfaserplatten 2-lagig (BSK); RoomName: Nasszelle DZ
Gipsfaserplatten 2-lagig (BSK) | WUN-H2-E01-072a | CEILING | Installationshöhe 0.764 m | 1166Dfl0000033989/02 | m² | Trockenbauarbeiten | 2 | 0.764 | 0 | 1 | Bekleidung | Installationshöhe | 0 | 0 | NEW | 2.5 | AllplanAttributes - ash_lichte Raumhöhe: 2.500000; OKFF: 0; RoomName: Nasszelle DZ
Gipskarton, imprägniert | WUN-H2-E01-072a | CEILING | B 0.1 m | 1166Dfl0000033989/03 | m² | Trockenbauarbeiten | 3 | 0.1 | 0 | 1 | Bekleidung | B | 0 | 0 | NEW | 2.5 | AllplanAttributes - Bezeichnung: Gipskarton, imprägniert; ash_lichte Raumhöhe: 2.500000; OKFF: 0; RoomName: Nasszelle DZ; Pset_CoveringCommon - AcousticRating: -
Gipsfaserplatten 2-lagig (BSK) | WUN-H2-E01-072a | CEILING | D1 0.001 m | 1166Dfl0000033989/04 | m² | Maler- und Lackierarbeiten | 4 | 0.001 | 0 | 1 | Bekleidung | D1 | 0 | 0 | NEW | 2.5 | AllplanAttributes - ash_lichte Raumhöhe: 2.500000; OKFF: 0; RoomName: Nasszelle DZ
 | WUN-H2-E01-072a | CLADDING | 50 0.001 m | 1166Sfl0000665061/01 | m² | Maler- und Lackierarbeiten | 1 | 0.001 | 0 | 1 | Seitenfläche | 50 | 150 | 2500 | NEW
a-sh Wandbelag | WUN-H2-E01-072a | CLADDING | 68 0.01 m | 1166Sfl0000667097/01 | m² | Maler- und Lackierarbeiten | 1 | 0.01 | 0 | 1 | Seitenfläche | 68 | 100 | 3000 | NEW | AllplanAttributes - Bezeichnung: a-sh Wandbelag; Attributset-Objekt: Covering
Fliesen Mosaik | WUN-H2-E01-073a | FLOORING | Fl2 0.15 m | 1166Bfl0000492417/01 | m² | Bodenbelagsarbeiten | 1 | 0.15 | 0 | 1 | Bodenfläche | Fl2 | 0 | 0 | NEW | AllplanAttributes - Bezeichnung: Fliesen Mosaik; Raumnr. Bauherr: 2.11_A2_02; ash B_Aufbau: B11; ash B_Rutschhemmung: R10; ash B_Bewertungsgruppe Barfußbereich: B
Fliesen | WUN-H2-E01-073a | FLOORING | Fl1 0.15 m | 1166Bfl0000033999/01 | m² | Bodenbelagsarbeiten | 1 | 0.15 | 0 | 1 | Bodenfläche | Fl1 | 0 | 0 | NEW | AllplanAttributes - Bezeichnung: Fliesen; Raumnr. Bauherr: 2.11_A2_02; ash B_Aufbau: B10; ash B_Rutschhemmung: R10
Gipsfaserplatten 2-lagig (BSK) | WUN-H2-E01-073a | CEILING | layer 0.036 m | 1166Dfl0000034000/01 | m² | Trockenbauarbeiten | 1 | 0.036 | 0 | 1 | Deckenfläche |  | 0 | 0 | NEW | 2.5 | AllplanAttributes - Bezeichnung: Gipsfaserplatten 2-lagig (BSK); RoomName: Nasszelle DZ
Gipsfaserplatten 2-lagig (BSK) | WUN-H2-E01-073a | CEILING | Installationshöhe 0.764 m | 1166Dfl0000034000/02 | m² | Trockenbauarbeiten | 2 | 0.764 | 0 | 1 | Bekleidung | Installationshöhe | 0 | 0 | NEW | 2.5 | AllplanAttributes - ash_lichte Raumhöhe: 2.500000; OKFF: 0; RoomName: Nasszelle DZ
Gipskarton, imprägniert | WUN-H2-E01-073a | CEILING | B 0.1 m | 1166Dfl0000034000/03 | m² | Trockenbauarbeiten | 3 | 0.1 | 0 | 1 | Bekleidung | B | 0 | 0 | NEW | 2.5 | AllplanAttributes - Bezeichnung: Gipskarton, imprägniert; ash_lichte Raumhöhe: 2.500000; OKFF: 0; RoomName: Nasszelle DZ; Pset_CoveringCommon - AcousticRating: -
Gipsfaserplatten 2-lagig (BSK) | WUN-H2-E01-073a | CEILING | D1 0.001 m | 1166Dfl0000034000/04 | m² | Maler- und Lackierarbeiten | 4 | 0.001 | 0 | 1 | Bekleidung | D1 | 0 | 0 | NEW | 2.5 | AllplanAttributes - ash_lichte Raumhöhe: 2.500000; OKFF: 0; RoomName: Nasszelle DZ
 | WUN-H2-E01-073a | CLADDING | 50 0.001 m | 1166Sfl0000665062/01 | m² | Maler- und Lackierarbeiten | 1 | 0.001 | 0 | 1 | Seitenfläche | 50 | 150 | 2500 | NEW
a-sh Wandbelag | WUN-H2-E01-073a | CLADDING | 68 0.01 m | 1166Sfl0000667166/01 | m² | Maler- und Lackierarbeiten | 1 | 0.01 | 0 | 1 | Seitenfläche | 68 | 100 | 3000 | NEW | AllplanAttributes - Bezeichnung: a-sh Wandbelag; Attributset-Objekt: Covering
Fliesen Mosaik | WUN-H2-E01-074a | FLOORING | Fl2 0.15 m | 1166Bfl0000492217/01 | m² | Bodenbelagsarbeiten | 1 | 0.15 | 0 | 1 | Bodenfläche | Fl2 | 0 | 0 | NEW | AllplanAttributes - Bezeichnung: Fliesen Mosaik; Raumnr. Bauherr: 2.11_A2_02; ash B_Aufbau: B11; ash B_Rutschhemmung: R10; ash B_Bewertungsgruppe Barfußbereich: B
Fliesen | WUN-H2-E01-074a | FLOORING | Fl1 0.15 m | 1166Bfl0000034010/01 | m² | Bodenbelagsarbeiten | 1 | 0.15 | 0 | 1 | Bodenfläche | Fl1 | 0 | 0 | NEW | AllplanAttributes - Bezeichnung: Fliesen; Raumnr. Bauherr: 2.11_A2_02; ash B_Aufbau: B10; ash B_Rutschhemmung: R10
Gipsfaserplatten 2-lagig (BSK) | WUN-H2-E01-074a | CEILING | layer 0.036 m | 1166Dfl0000034011/01 | m² | Trockenbauarbeiten | 1 | 0.036 | 0 | 1 | Deckenfläche |  | 0 | 0 | NEW | 2.5 | AllplanAttributes - Bezeichnung: Gipsfaserplatten 2-lagig (BSK); RoomName: Nasszelle DZ
Gipsfaserplatten 2-lagig (BSK) | WUN-H2-E01-074a | CEILING | Installationshöhe 0.764 m | 1166Dfl0000034011/02 | m² | Trockenbauarbeiten | 2 | 0.764 | 0 | 1 | Bekleidung | Installationshöhe | 0 | 0 | NEW | 2.5 | AllplanAttributes - ash_lichte Raumhöhe: 2.500000; OKFF: 0; RoomName: Nasszelle DZ
Gipskarton, imprägniert | WUN-H2-E01-074a | CEILING | B 0.1 m | 1166Dfl0000034011/03 | m² | Trockenbauarbeiten | 3 | 0.1 | 0 | 1 | Bekleidung | B | 0 | 0 | NEW | 2.5 | AllplanAttributes - Bezeichnung: Gipskarton, imprägniert; ash_lichte Raumhöhe: 2.500000; OKFF: 0; RoomName: Nasszelle DZ; Pset_CoveringCommon - AcousticRating: -
Gipsfaserplatten 2-lagig (BSK) | WUN-H2-E01-074a | CEILING | D1 0.001 m | 1166Dfl0000034011/04 | m² | Maler- und Lackierarbeiten | 4 | 0.001 | 0 | 1 | Bekleidung | D1 | 0 | 0 | NEW | 2.5 | AllplanAttributes - ash_lichte Raumhöhe: 2.500000; OKFF: 0; RoomName: Nasszelle DZ
 | WUN-H2-E01-074a | CLADDING | 50 0.001 m | 1166Sfl0000665063/01 | m² | Maler- und Lackierarbeiten | 1 | 0.001 | 0 | 1 | Seitenfläche | 50 | 150 | 2500 | NEW
a-sh Wandbelag | WUN-H2-E01-074a | CLADDING | 68 0.01 m | 1166Sfl0000667235/01 | m² | Maler- und Lackierarbeiten | 1 | 0.01 | 0 | 1 | Seitenfläche | 68 | 100 | 3000 | NEW | AllplanAttributes - Bezeichnung: a-sh Wandbelag; Attributset-Objekt: Covering
Fliesen Mosaik | WUN-H2-E01-092a | FLOORING | Fl2 0.15 m | 1166Bfl0000491617/01 | m² | Bodenbelagsarbeiten | 1 | 0.15 | 0 | 1 | Bodenfläche | Fl2 | 0 | 0 | NEW | AllplanAttributes - Bezeichnung: Fliesen Mosaik; Raumnr. Bauherr: 2.11_A2_02; ash B_Aufbau: B11; ash B_Rutschhemmung: R10; ash B_Bewertungsgruppe Barfußbereich: B
Fliesen | WUN-H2-E01-092a | FLOORING | Fl1 0.15 m | 1166Bfl0000034466/01 | m² | Bodenbelagsarbeiten | 1 | 0.15 | 0 | 1 | Bodenfläche | Fl1 | 0 | 0 | NEW | AllplanAttributes - Bezeichnung: Fliesen; Raumnr. Bauherr: 2.11_A2_02; ash B_Aufbau: B10; ash B_Rutschhemmung: R10
Gipsfaserplatten 2-lagig (BSK) | WUN-H2-E01-092a | CEILING | layer 0.036 m | 1166Dfl0000034467/01 | m² | Trockenbauarbeiten | 1 | 0.036 | 0 | 1 | Deckenfläche |  | 0 | 0 | NEW | 2.5 | AllplanAttributes - Bezeichnung: Gipsfaserplatten 2-lagig (BSK); RoomName: Nasszelle DZ
Gipsfaserplatten 2-lagig (BSK) | WUN-H2-E01-092a | CEILING | Installationshöhe 0.764 m | 1166Dfl0000034467/02 | m² | Trockenbauarbeiten | 2 | 0.764 | 0 | 1 | Bekleidung | Installationshöhe | 0 | 0 | NEW | 2.5 | AllplanAttributes - ash_lichte Raumhöhe: 2.500000; OKFF: 0; RoomName: Nasszelle DZ
Gipskarton, imprägniert | WUN-H2-E01-092a | CEILING | B 0.1 m | 1166Dfl0000034467/03 | m² | Trockenbauarbeiten | 3 | 0.1 | 0 | 1 | Bekleidung | B | 0 | 0 | NEW | 2.5 | AllplanAttributes - Bezeichnung: Gipskarton, imprägniert; ash_lichte Raumhöhe: 2.500000; OKFF: 0; RoomName: Nasszelle DZ; Pset_CoveringCommon - AcousticRating: -
Gipsfaserplatten 2-lagig (BSK) | WUN-H2-E01-092a | CEILING | D1 0.001 m | 1166Dfl0000034467/04 | m² | Maler- und Lackierarbeiten | 4 | 0.001 | 0 | 1 | Bekleidung | D1 | 0 | 0 | NEW | 2.5 | AllplanAttributes - ash_lichte Raumhöhe: 2.500000; OKFF: 0; RoomName: Nasszelle DZ
 | WUN-H2-E01-092a | CLADDING | 50 0.001 m | 1166Sfl0000665064/01 | m² | Maler- und Lackierarbeiten | 1 | 0.001 | 0 | 1 | Seitenfläche | 50 | 150 | 2500 | NEW
a-sh Wandbelag | WUN-H2-E01-092a | CLADDING | 68 0.01 m | 1166Sfl0000666821/01 | m² | Maler- und Lackierarbeiten | 1 | 0.01 | 0 | 1 | Seitenfläche | 68 | 100 | 3000 | NEW | AllplanAttributes - Bezeichnung: a-sh Wandbelag; Attributset-Objekt: Covering
Fliesen Mosaik | WUN-H2-E01-020a | FLOORING | Fl2 0.15 m | 1166Bfl0000489004/01 | m² | Bodenbelagsarbeiten | 1 | 0.15 | 0 | 1 | Bodenfläche | Fl2 | 0 | 0 | NEW | AllplanAttributes - Bezeichnung: Fliesen Mosaik; Raumnr. Bauherr: 2.11_A2_02; ash B_Aufbau: B11; ash B_Rutschhemmung: R10; ash B_Bewertungsgruppe Barfußbereich: B
Fliesen | WUN-H2-E01-020a | FLOORING | Fl1 0.15 m | 1166Bfl0000033640/01 | m² | Bodenbelagsarbeiten | 1 | 0.15 | 0 | 1 | Bodenfläche | Fl1 | 0 | 0 | NEW | AllplanAttributes - Bezeichnung: Fliesen; Raumnr. Bauherr: 2.11_A2_02; ash B_Aufbau: B10; ash B_Rutschhemmung: R10
Gipsfaserplatten 2-lagig (BSK) | WUN-H2-E01-020a | CEILING | layer 0.036 m | 1166Dfl0000033641/01 | m² | Trockenbauarbeiten | 1 | 0.036 | 0 | 1 | Deckenfläche |  | 0 | 0 | NEW | 2.5 | AllplanAttributes - Bezeichnung: Gipsfaserplatten 2-lagig (BSK); RoomName: Nasszelle DZ
Gipsfaserplatten 2-lagig (BSK) | WUN-H2-E01-020a | CEILING | Installationshöhe 0.764 m | 1166Dfl0000033641/02 | m² | Trockenbauarbeiten | 2 | 0.764 | 0 | 1 | Bekleidung | Installationshöhe | 0 | 0 | NEW | 2.5 | AllplanAttributes - ash_lichte Raumhöhe: 2.500000; OKFF: 0; RoomName: Nasszelle DZ
Gipskarton, imprägniert | WUN-H2-E01-020a | CEILING | B 0.1 m | 1166Dfl0000033641/03 | m² | Trockenbauarbeiten | 3 | 0.1 | 0 | 1 | Bekleidung | B | 0 | 0 | NEW | 2.5 | AllplanAttributes - Bezeichnung: Gipskarton, imprägniert; ash_lichte Raumhöhe: 2.500000; OKFF: 0; RoomName: Nasszelle DZ; Pset_CoveringCommon - AcousticRating: -
Gipsfaserplatten 2-lagig (BSK) | WUN-H2-E01-020a | CEILING | D1 0.001 m | 1166Dfl0000033641/04 | m² | Maler- und Lackierarbeiten | 4 | 0.001 | 0 | 1 | Bekleidung | D1 | 0 | 0 | NEW | 2.5 | AllplanAttributes - ash_lichte Raumhöhe: 2.500000; OKFF: 0; RoomName: Nasszelle DZ
 | WUN-H2-E01-020a | CLADDING | 50 0.001 m | 1166Sfl0000665065/01 | m² | Maler- und Lackierarbeiten | 1 | 0.001 | 0 | 1 | Seitenfläche | 50 | 150 | 2500 | NEW
a-sh Wandbelag | WUN-H2-E01-020a | CLADDING | 68 0.01 m | 1166Sfl0000666214/01 | m² | Maler- und Lackierarbeiten | 1 | 0.01 | 0 | 1 | Seitenfläche | 68 | 100 | 3000 | NEW | AllplanAttributes - Bezeichnung: a-sh Wandbelag; Attributset-Objekt: Covering
Fliesen Mosaik | WUN-H2-E01-021a | FLOORING | Fl2 0.15 m | 1166Bfl0000488804/01 | m² | Bodenbelagsarbeiten | 1 | 0.15 | 0 | 1 | Bodenfläche | Fl2 | 0 | 0 | NEW | AllplanAttributes - Bezeichnung: Fliesen Mosaik; Raumnr. Bauherr: 2.11_A2_02; ash B_Aufbau: B11; ash B_Rutschhemmung: R10; ash B_Bewertungsgruppe Barfußbereich: B
Fliesen | WUN-H2-E01-021a | FLOORING | Fl1 0.15 m | 1166Bfl0000033651/01 | m² | Bodenbelagsarbeiten | 1 | 0.15 | 0 | 1 | Bodenfläche | Fl1 | 0 | 0 | NEW | AllplanAttributes - Bezeichnung: Fliesen; Raumnr. Bauherr: 2.11_A2_02; ash B_Aufbau: B10; ash B_Rutschhemmung: R10
Gipsfaserplatten 2-lagig (BSK) | WUN-H2-E01-021a | CEILING | layer 0.036 m | 1166Dfl0000033652/01 | m² | Trockenbauarbeiten | 1 | 0.036 | 0 | 1 | Deckenfläche |  | 0 | 0 | NEW | 2.5 | AllplanAttributes - Bezeichnung: Gipsfaserplatten 2-lagig (BSK); RoomName: Nasszelle DZ
Gipsfaserplatten 2-lagig (BSK) | WUN-H2-E01-021a | CEILING | Installationshöhe 0.764 m | 1166Dfl0000033652/02 | m² | Trockenbauarbeiten | 2 | 0.764 | 0 | 1 | Bekleidung | Installationshöhe | 0 | 0 | NEW | 2.5 | AllplanAttributes - ash_lichte Raumhöhe: 2.500000; OKFF: 0; RoomName: Nasszelle DZ
Gipskarton, imprägniert | WUN-H2-E01-021a | CEILING | B 0.1 m | 1166Dfl0000033652/03 | m² | Trockenbauarbeiten | 3 | 0.1 | 0 | 1 | Bekleidung | B | 0 | 0 | NEW | 2.5 | AllplanAttributes - Bezeichnung: Gipskarton, imprägniert; ash_lichte Raumhöhe: 2.500000; OKFF: 0; RoomName: Nasszelle DZ; Pset_CoveringCommon - AcousticRating: -
Gipsfaserplatten 2-lagig (BSK) | WUN-H2-E01-021a | CEILING | D1 0.001 m | 1166Dfl0000033652/04 | m² | Maler- und Lackierarbeiten | 4 | 0.001 | 0 | 1 | Bekleidung | D1 | 0 | 0 | NEW | 2.5 | AllplanAttributes - ash_lichte Raumhöhe: 2.500000; OKFF: 0; RoomName: Nasszelle DZ
 | WUN-H2-E01-021a | CLADDING | 50 0.001 m | 1166Sfl0000665066/01 | m² | Maler- und Lackierarbeiten | 1 | 0.001 | 0 | 1 | Seitenfläche | 50 | 150 | 2500 | NEW
a-sh Wandbelag | WUN-H2-E01-021a | CLADDING | 68 0.01 m | 1166Sfl0000666145/01 | m² | Maler- und Lackierarbeiten | 1 | 0.01 | 0 | 1 | Seitenfläche | 68 | 100 | 3000 | NEW | AllplanAttributes - Bezeichnung: a-sh Wandbelag; Attributset-Objekt: Covering
Fliesen Mosaik | WUN-H2-E01-022a | FLOORING | Fl2 0.15 m | 1166Bfl0000488604/01 | m² | Bodenbelagsarbeiten | 1 | 0.15 | 0 | 1 | Bodenfläche | Fl2 | 0 | 0 | NEW | AllplanAttributes - Bezeichnung: Fliesen Mosaik; Raumnr. Bauherr: 2.11_A2_02; ash B_Aufbau: B11; ash B_Rutschhemmung: R10; ash B_Bewertungsgruppe Barfußbereich: B
Fliesen | WUN-H2-E01-022a | FLOORING | Fl1 0.15 m | 1166Bfl0000033662/01 | m² | Bodenbelagsarbeiten | 1 | 0.15 | 0 | 1 | Bodenfläche | Fl1 | 0 | 0 | NEW | AllplanAttributes - Bezeichnung: Fliesen; Raumnr. Bauherr: 2.11_A2_02; ash B_Aufbau: B10; ash B_Rutschhemmung: R10
Gipsfaserplatten 2-lagig (BSK) | WUN-H2-E01-022a | CEILING | layer 0.036 m | 1166Dfl0000033663/01 | m² | Trockenbauarbeiten | 1 | 0.036 | 0 | 1 | Deckenfläche |  | 0 | 0 | NEW | 2.5 | AllplanAttributes - Bezeichnung: Gipsfaserplatten 2-lagig (BSK); RoomName: Nasszelle DZ
Gipsfaserplatten 2-lagig (BSK) | WUN-H2-E01-022a | CEILING | Installationshöhe 0.764 m | 1166Dfl0000033663/02 | m² | Trockenbauarbeiten | 2 | 0.764 | 0 | 1 | Bekleidung | Installationshöhe | 0 | 0 | NEW | 2.5 | AllplanAttributes - ash_lichte Raumhöhe: 2.500000; OKFF: 0; RoomName: Nasszelle DZ
Gipskarton, imprägniert | WUN-H2-E01-022a | CEILING | B 0.1 m | 1166Dfl0000033663/03 | m² | Trockenbauarbeiten | 3 | 0.1 | 0 | 1 | Bekleidung | B | 0 | 0 | NEW | 2.5 | AllplanAttributes - Bezeichnung: Gipskarton, imprägniert; ash_lichte Raumhöhe: 2.500000; OKFF: 0; RoomName: Nasszelle DZ; Pset_CoveringCommon - AcousticRating: -
Gipsfaserplatten 2-lagig (BSK) | WUN-H2-E01-022a | CEILING | D1 0.001 m | 1166Dfl0000033663/04 | m² | Maler- und Lackierarbeiten | 4 | 0.001 | 0 | 1 | Bekleidung | D1 | 0 | 0 | NEW | 2.5 | AllplanAttributes - ash_lichte Raumhöhe: 2.500000; OKFF: 0; RoomName: Nasszelle DZ
 | WUN-H2-E01-022a | CLADDING | 50 0.001 m | 1166Sfl0000665067/01 | m² | Maler- und Lackierarbeiten | 1 | 0.001 | 0 | 1 | Seitenfläche | 50 | 150 | 2500 | NEW
a-sh Wandbelag | WUN-H2-E01-022a | CLADDING | 68 0.01 m | 1166Sfl0000666076/01 | m² | Maler- und Lackierarbeiten | 1 | 0.01 | 0 | 1 | Seitenfläche | 68 | 100 | 3000 | NEW | AllplanAttributes - Bezeichnung: a-sh Wandbelag; Attributset-Objekt: Covering
Fliesen Mosaik | WUN-H2-E01-023a | FLOORING | Fl2 0.15 m | 1166Bfl0000488404/01 | m² | Bodenbelagsarbeiten | 1 | 0.15 | 0 | 1 | Bodenfläche | Fl2 | 0 | 0 | NEW | AllplanAttributes - Bezeichnung: Fliesen Mosaik; Raumnr. Bauherr: 2.11_A2_02; ash B_Aufbau: B11; ash B_Rutschhemmung: R10; ash B_Bewertungsgruppe Barfußbereich: B
Fliesen | WUN-H2-E01-023a | FLOORING | Fl1 0.15 m | 1166Bfl0000033673/01 | m² | Bodenbelagsarbeiten | 1 | 0.15 | 0 | 1 | Bodenfläche | Fl1 | 0 | 0 | NEW | AllplanAttributes - Bezeichnung: Fliesen; Raumnr. Bauherr: 2.11_A2_02; ash B_Aufbau: B10; ash B_Rutschhemmung: R10
Gipsfaserplatten 2-lagig (BSK) | WUN-H2-E01-023a | CEILING | layer 0.036 m | 1166Dfl0000033674/01 | m² | Trockenbauarbeiten | 1 | 0.036 | 0 | 1 | Deckenfläche |  | 0 | 0 | NEW | 2.5 | AllplanAttributes - Bezeichnung: Gipsfaserplatten 2-lagig (BSK); RoomName: Nasszelle DZ
Gipsfaserplatten 2-lagig (BSK) | WUN-H2-E01-023a | CEILING | Installationshöhe 0.764 m | 1166Dfl0000033674/02 | m² | Trockenbauarbeiten | 2 | 0.764 | 0 | 1 | Bekleidung | Installationshöhe | 0 | 0 | NEW | 2.5 | AllplanAttributes - ash_lichte Raumhöhe: 2.500000; OKFF: 0; RoomName: Nasszelle DZ
Gipskarton, imprägniert | WUN-H2-E01-023a | CEILING | B 0.1 m | 1166Dfl0000033674/03 | m² | Trockenbauarbeiten | 3 | 0.1 | 0 | 1 | Bekleidung | B | 0 | 0 | NEW | 2.5 | AllplanAttributes - Bezeichnung: Gipskarton, imprägniert; ash_lichte Raumhöhe: 2.500000; OKFF: 0; RoomName: Nasszelle DZ; Pset_CoveringCommon - AcousticRating: -
Gipsfaserplatten 2-lagig (BSK) | WUN-H2-E01-023a | CEILING | D1 0.001 m | 1166Dfl0000033674/04 | m² | Maler- und Lackierarbeiten | 4 | 0.001 | 0 | 1 | Bekleidung | D1 | 0 | 0 | NEW | 2.5 | AllplanAttributes - ash_lichte Raumhöhe: 2.500000; OKFF: 0; RoomName: Nasszelle DZ
 | WUN-H2-E01-023a | CLADDING | 50 0.001 m | 1166Sfl0000665068/01 | m² | Maler- und Lackierarbeiten | 1 | 0.001 | 0 | 1 | Seitenfläche | 50 | 150 | 2500 | NEW
a-sh Wandbelag | WUN-H2-E01-023a | CLADDING | 68 0.01 m | 1166Sfl0000666007/01 | m² | Maler- und Lackierarbeiten | 1 | 0.01 | 0 | 1 | Seitenfläche | 68 | 100 | 3000 | NEW | AllplanAttributes - Bezeichnung: a-sh Wandbelag; Attributset-Objekt: Covering
Fliesen Mosaik | WUN-H2-E01-024a | FLOORING | Fl2 0.15 m | 1166Bfl0000488204/01 | m² | Bodenbelagsarbeiten | 1 | 0.15 | 0 | 1 | Bodenfläche | Fl2 | 0 | 0 | NEW | AllplanAttributes - Bezeichnung: Fliesen Mosaik; Raumnr. Bauherr: 2.11_A2_02; ash B_Aufbau: B11; ash B_Rutschhemmung: R10; ash B_Bewertungsgruppe Barfußbereich: B
Fliesen | WUN-H2-E01-024a | FLOORING | Fl1 0.15 m | 1166Bfl0000033684/01 | m² | Bodenbelagsarbeiten | 1 | 0.15 | 0 | 1 | Bodenfläche | Fl1 | 0 | 0 | NEW | AllplanAttributes - Bezeichnung: Fliesen; Raumnr. Bauherr: 2.11_A2_02; ash B_Aufbau: B10; ash B_Rutschhemmung: R10
Gipsfaserplatten 2-lagig (BSK) | WUN-H2-E01-024a | CEILING | layer 0.036 m | 1166Dfl0000033685/01 | m² | Trockenbauarbeiten | 1 | 0.036 | 0 | 1 | Deckenfläche |  | 0 | 0 | NEW | 2.5 | AllplanAttributes - Bezeichnung: Gipsfaserplatten 2-lagig (BSK); RoomName: Nasszelle DZ
Gipsfaserplatten 2-lagig (BSK) | WUN-H2-E01-024a | CEILING | Installationshöhe 0.764 m | 1166Dfl0000033685/02 | m² | Trockenbauarbeiten | 2 | 0.764 | 0 | 1 | Bekleidung | Installationshöhe | 0 | 0 | NEW | 2.5 | AllplanAttributes - ash_lichte Raumhöhe: 2.500000; OKFF: 0; RoomName: Nasszelle DZ
Gipskarton, imprägniert | WUN-H2-E01-024a | CEILING | B 0.1 m | 1166Dfl0000033685/03 | m² | Trockenbauarbeiten | 3 | 0.1 | 0 | 1 | Bekleidung | B | 0 | 0 | NEW | 2.5 | AllplanAttributes - Bezeichnung: Gipskarton, imprägniert; ash_lichte Raumhöhe: 2.500000; OKFF: 0; RoomName: Nasszelle DZ; Pset_CoveringCommon - AcousticRating: -
Gipsfaserplatten 2-lagig (BSK) | WUN-H2-E01-024a | CEILING | D1 0.001 m | 1166Dfl0000033685/04 | m² | Maler- und Lackierarbeiten | 4 | 0.001 | 0 | 1 | Bekleidung | D1 | 0 | 0 | NEW | 2.5 | AllplanAttributes - ash_lichte Raumhöhe: 2.500000; OKFF: 0; RoomName: Nasszelle DZ
 | WUN-H2-E01-024a | CLADDING | 50 0.001 m | 1166Sfl0000665069/01 | m² | Maler- und Lackierarbeiten | 1 | 0.001 | 0 | 1 | Seitenfläche | 50 | 150 | 2500 | NEW
a-sh Wandbelag | WUN-H2-E01-024a | CLADDING | 68 0.01 m | 1166Sfl0000665938/01 | m² | Maler- und Lackierarbeiten | 1 | 0.01 | 0 | 1 | Seitenfläche | 68 | 100 | 3000 | NEW | AllplanAttributes - Bezeichnung: a-sh Wandbelag; Attributset-Objekt: Covering
Fliesen Mosaik | WUN-H2-E01-025a | FLOORING | Fl2 0.15 m | 1166Bfl0000474961/01 | m² | Bodenbelagsarbeiten | 1 | 0.15 | 0 | 1 | Bodenfläche | Fl2 | 0 | 0 | NEW | AllplanAttributes - Bezeichnung: Fliesen Mosaik; Raumnr. Bauherr: 2.11_A2_02; ash B_Aufbau: B11; ash B_Rutschhemmung: R10; ash B_Bewertungsgruppe Barfußbereich: B
Fliesen | WUN-H2-E01-025a | FLOORING | Fl1 0.15 m | 1166Bfl0000033695/01 | m² | Bodenbelagsarbeiten | 1 | 0.15 | 0 | 1 | Bodenfläche | Fl1 | 0 | 0 | NEW | AllplanAttributes - Bezeichnung: Fliesen; Raumnr. Bauherr: 2.11_A2_02; ash B_Aufbau: B10; ash B_Rutschhemmung: R10
Gipsfaserplatten 2-lagig (BSK) | WUN-H2-E01-025a | CEILING | layer 0.036 m | 1166Dfl0000033696/01 | m² | Trockenbauarbeiten | 1 | 0.036 | 0 | 1 | Deckenfläche |  | 0 | 0 | NEW | 2.5 | AllplanAttributes - Bezeichnung: Gipsfaserplatten 2-lagig (BSK); RoomName: Nasszelle DZ
Gipsfaserplatten 2-lagig (BSK) | WUN-H2-E01-025a | CEILING | Installationshöhe 0.764 m | 1166Dfl0000033696/02 | m² | Trockenbauarbeiten | 2 | 0.764 | 0 | 1 | Bekleidung | Installationshöhe | 0 | 0 | NEW | 2.5 | AllplanAttributes - ash_lichte Raumhöhe: 2.500000; OKFF: 0; RoomName: Nasszelle DZ
Gipskarton, imprägniert | WUN-H2-E01-025a | CEILING | B 0.1 m | 1166Dfl0000033696/03 | m² | Trockenbauarbeiten | 3 | 0.1 | 0 | 1 | Bekleidung | B | 0 | 0 | NEW | 2.5 | AllplanAttributes - Bezeichnung: Gipskarton, imprägniert; ash_lichte Raumhöhe: 2.500000; OKFF: 0; RoomName: Nasszelle DZ; Pset_CoveringCommon - AcousticRating: -
Gipsfaserplatten 2-lagig (BSK) | WUN-H2-E01-025a | CEILING | D1 0.001 m | 1166Dfl0000033696/04 | m² | Maler- und Lackierarbeiten | 4 | 0.001 | 0 | 1 | Bekleidung | D1 | 0 | 0 | NEW | 2.5 | AllplanAttributes - ash_lichte Raumhöhe: 2.500000; OKFF: 0; RoomName: Nasszelle DZ
 | WUN-H2-E01-025a | CLADDING | 50 0.001 m | 1166Sfl0000665070/01 | m² | Maler- und Lackierarbeiten | 1 | 0.001 | 0 | 1 | Seitenfläche | 50 | 150 | 2500 | NEW
a-sh Wandbelag | WUN-H2-E01-025a | CLADDING | 68 0.01 m | 1166Sfl0000665869/01 | m² | Maler- und Lackierarbeiten | 1 | 0.01 | 0 | 1 | Seitenfläche | 68 | 100 | 3000 | NEW | AllplanAttributes - Bezeichnung: a-sh Wandbelag; Attributset-Objekt: Covering
Fliesen Mosaik | WUN-H2-E01-095a | FLOORING | Fl2 0.15 m | 1166Bfl0000491017/01 | m² | Bodenbelagsarbeiten | 1 | 0.15 | 0 | 1 | Bodenfläche | Fl2 | 0 | 0 | NEW | AllplanAttributes - Bezeichnung: Fliesen Mosaik; Raumnr. Bauherr: 2.11_A2_02; ash B_Aufbau: B11; ash B_Rutschhemmung: R10; ash B_Bewertungsgruppe Barfußbereich: B
Fliesen | WUN-H2-E01-095a | FLOORING | Fl1 0.15 m | 1166Bfl0000034525/01 | m² | Bodenbelagsarbeiten | 1 | 0.15 | 0 | 1 | Bodenfläche | Fl1 | 0 | 0 | NEW | AllplanAttributes - Bezeichnung: Fliesen; Raumnr. Bauherr: 2.11_A2_02; ash B_Aufbau: B10; ash B_Rutschhemmung: R10
Gipsfaserplatten 2-lagig (BSK) | WUN-H2-E01-095a | CEILING | layer 0.036 m | 1166Dfl0000034526/01 | m² | Trockenbauarbeiten | 1 | 0.036 | 0 | 1 | Deckenfläche |  | 0 | 0 | NEW | 2.5 | AllplanAttributes - Bezeichnung: Gipsfaserplatten 2-lagig (BSK); RoomName: Nasszelle DZ
Gipsfaserplatten 2-lagig (BSK) | WUN-H2-E01-095a | CEILING | Installationshöhe 0.764 m | 1166Dfl0000034526/02 | m² | Trockenbauarbeiten | 2 | 0.764 | 0 | 1 | Bekleidung | Installationshöhe | 0 | 0 | NEW | 2.5 | AllplanAttributes - ash_lichte Raumhöhe: 2.500000; OKFF: 0; RoomName: Nasszelle DZ
Gipskarton, imprägniert | WUN-H2-E01-095a | CEILING | B 0.1 m | 1166Dfl0000034526/03 | m² | Trockenbauarbeiten | 3 | 0.1 | 0 | 1 | Bekleidung | B | 0 | 0 | NEW | 2.5 | AllplanAttributes - Bezeichnung: Gipskarton, imprägniert; ash_lichte Raumhöhe: 2.500000; OKFF: 0; RoomName: Nasszelle DZ; Pset_CoveringCommon - AcousticRating: -
Gipsfaserplatten 2-lagig (BSK) | WUN-H2-E01-095a | CEILING | D1 0.001 m | 1166Dfl0000034526/04 | m² | Maler- und Lackierarbeiten | 4 | 0.001 | 0 | 1 | Bekleidung | D1 | 0 | 0 | NEW | 2.5 | AllplanAttributes - ash_lichte Raumhöhe: 2.500000; OKFF: 0; RoomName: Nasszelle DZ
 | WUN-H2-E01-095a | CLADDING | 50 0.001 m | 1166Sfl0000665071/01 | m² | Maler- und Lackierarbeiten | 1 | 0.001 | 0 | 1 | Seitenfläche | 50 | 150 | 2500 | NEW
a-sh Wandbelag | WUN-H2-E01-095a | CLADDING | 68 0.01 m | 1166Sfl0000666739/01 | m² | Maler- und Lackierarbeiten | 1 | 0.01 | 0 | 1 | Seitenfläche | 68 | 100 | 3000 | NEW | AllplanAttributes - Bezeichnung: a-sh Wandbelag; Attributset-Objekt: Covering
Fliesen Mosaik | WUN-H2-E01-094a | FLOORING | Fl2 0.15 m | 1166Bfl0000491217/01 | m² | Bodenbelagsarbeiten | 1 | 0.15 | 0 | 1 | Bodenfläche | Fl2 | 0 | 0 | NEW | AllplanAttributes - Bezeichnung: Fliesen Mosaik; Raumnr. Bauherr: 2.11_A2_02; ash B_Aufbau: B11; ash B_Rutschhemmung: R10; ash B_Bewertungsgruppe Barfußbereich: B
Fliesen | WUN-H2-E01-094a | FLOORING | Fl1 0.15 m | 1166Bfl0000034501/01 | m² | Bodenbelagsarbeiten | 1 | 0.15 | 0 | 1 | Bodenfläche | Fl1 | 0 | 0 | NEW | AllplanAttributes - Bezeichnung: Fliesen; Raumnr. Bauherr: 2.11_A2_02; ash B_Aufbau: B10; ash B_Rutschhemmung: R10
Gipsfaserplatten 2-lagig (BSK) | WUN-H2-E01-094a | CEILING | layer 0.036 m | 1166Dfl0000034502/01 | m² | Trockenbauarbeiten | 1 | 0.036 | 0 | 1 | Deckenfläche |  | 0 | 0 | NEW | 2.5 | AllplanAttributes - Bezeichnung: Gipsfaserplatten 2-lagig (BSK); RoomName: Nasszelle DZ
Gipsfaserplatten 2-lagig (BSK) | WUN-H2-E01-094a | CEILING | Installationshöhe 0.764 m | 1166Dfl0000034502/02 | m² | Trockenbauarbeiten | 2 | 0.764 | 0 | 1 | Bekleidung | Installationshöhe | 0 | 0 | NEW | 2.5 | AllplanAttributes - ash_lichte Raumhöhe: 2.500000; OKFF: 0; RoomName: Nasszelle DZ
Gipskarton, imprägniert | WUN-H2-E01-094a | CEILING | B 0.1 m | 1166Dfl0000034502/03 | m² | Trockenbauarbeiten | 3 | 0.1 | 0 | 1 | Bekleidung | B | 0 | 0 | NEW | 2.5 | AllplanAttributes - Bezeichnung: Gipskarton, imprägniert; ash_lichte Raumhöhe: 2.500000; OKFF: 0; RoomName: Nasszelle DZ; Pset_CoveringCommon - AcousticRating: -
Gipsfaserplatten 2-lagig (BSK) | WUN-H2-E01-094a | CEILING | D1 0.001 m | 1166Dfl0000034502/04 | m² | Maler- und Lackierarbeiten | 4 | 0.001 | 0 | 1 | Bekleidung | D1 | 0 | 0 | NEW | 2.5 | AllplanAttributes - ash_lichte Raumhöhe: 2.500000; OKFF: 0; RoomName: Nasszelle DZ
 | WUN-H2-E01-094a | CLADDING | 50 0.001 m | 1166Sfl0000665072/01 | m² | Maler- und Lackierarbeiten | 1 | 0.001 | 0 | 1 | Seitenfläche | 50 | 150 | 2500 | NEW
a-sh Wandbelag | WUN-H2-E01-094a | CLADDING | 68 0.01 m | 1166Sfl0000666809/01 | m² | Maler- und Lackierarbeiten | 1 | 0.01 | 0 | 1 | Seitenfläche | 68 | 100 | 3000 | NEW | AllplanAttributes - Bezeichnung: a-sh Wandbelag; Attributset-Objekt: Covering
Fliesen Mosaik | WUN-H2-E01-093a | FLOORING | Fl2 0.15 m | 1166Bfl0000491417/01 | m² | Bodenbelagsarbeiten | 1 | 0.15 | 0 | 1 | Bodenfläche | Fl2 | 0 | 0 | NEW | AllplanAttributes - Bezeichnung: Fliesen Mosaik; Raumnr. Bauherr: 2.11_A2_02; ash B_Aufbau: B11; ash B_Rutschhemmung: R10; ash B_Bewertungsgruppe Barfußbereich: B
Fliesen | WUN-H2-E01-093a | FLOORING | Fl1 0.15 m | 1166Bfl0000034477/01 | m² | Bodenbelagsarbeiten | 1 | 0.15 | 0 | 1 | Bodenfläche | Fl1 | 0 | 0 | NEW | AllplanAttributes - Bezeichnung: Fliesen; Raumnr. Bauherr: 2.11_A2_02; ash B_Aufbau: B10; ash B_Rutschhemmung: R10
Gipsfaserplatten 2-lagig (BSK) | WUN-H2-E01-093a | CEILING | layer 0.036 m | 1166Dfl0000034478/01 | m² | Trockenbauarbeiten | 1 | 0.036 | 0 | 1 | Deckenfläche |  | 0 | 0 | NEW | 2.5 | AllplanAttributes - Bezeichnung: Gipsfaserplatten 2-lagig (BSK); RoomName: Nasszelle DZ
Gipsfaserplatten 2-lagig (BSK) | WUN-H2-E01-093a | CEILING | Installationshöhe 0.764 m | 1166Dfl0000034478/02 | m² | Trockenbauarbeiten | 2 | 0.764 | 0 | 1 | Bekleidung | Installationshöhe | 0 | 0 | NEW | 2.5 | AllplanAttributes - ash_lichte Raumhöhe: 2.500000; OKFF: 0; RoomName: Nasszelle DZ
Gipskarton, imprägniert | WUN-H2-E01-093a | CEILING | B 0.1 m | 1166Dfl0000034478/03 | m² | Trockenbauarbeiten | 3 | 0.1 | 0 | 1 | Bekleidung | B | 0 | 0 | NEW | 2.5 | AllplanAttributes - Bezeichnung: Gipskarton, imprägniert; ash_lichte Raumhöhe: 2.500000; OKFF: 0; RoomName: Nasszelle DZ; Pset_CoveringCommon - AcousticRating: -
Gipsfaserplatten 2-lagig (BSK) | WUN-H2-E01-093a | CEILING | D1 0.001 m | 1166Dfl0000034478/04 | m² | Maler- und Lackierarbeiten | 4 | 0.001 | 0 | 1 | Bekleidung | D1 | 0 | 0 | NEW | 2.5 | AllplanAttributes - ash_lichte Raumhöhe: 2.500000; OKFF: 0; RoomName: Nasszelle DZ
 | WUN-H2-E01-093a | CLADDING | 50 0.001 m | 1166Sfl0000665073/01 | m² | Maler- und Lackierarbeiten | 1 | 0.001 | 0 | 1 | Seitenfläche | 50 | 150 | 2500 | NEW
a-sh Wandbelag | WUN-H2-E01-093a | CLADDING | 68 0.01 m | 1166Sfl0000666817/01 | m² | Maler- und Lackierarbeiten | 1 | 0.01 | 0 | 1 | Seitenfläche | 68 | 100 | 3000 | NEW | AllplanAttributes - Bezeichnung: a-sh Wandbelag; Attributset-Objekt: Covering
Fliesen Mosaik | WUN-H2-E01-068a | FLOORING | Fl2 0.15 m | 1166Bfl0000493417/01 | m² | Bodenbelagsarbeiten | 1 | 0.15 | 0 | 1 | Bodenfläche | Fl2 | 0 | 0 | NEW | AllplanAttributes - Bezeichnung: Fliesen Mosaik; Raumnr. Bauherr: 2.11_A2_02; ash B_Aufbau: B11; ash B_Rutschhemmung: R10; ash B_Bewertungsgruppe Barfußbereich: B
Fliesen | WUN-H2-E01-068a | FLOORING | Fl1 0.15 m | 1166Bfl0000033944/01 | m² | Bodenbelagsarbeiten | 1 | 0.15 | 0 | 1 | Bodenfläche | Fl1 | 0 | 0 | NEW | AllplanAttributes - Bezeichnung: Fliesen; Raumnr. Bauherr: 2.11_A2_02; ash B_Aufbau: B10; ash B_Rutschhemmung: R10
Gipsfaserplatten 2-lagig (BSK) | WUN-H2-E01-068a | CEILING | layer 0.036 m | 1166Dfl0000033945/01 | m² | Trockenbauarbeiten | 1 | 0.036 | 0 | 1 | Deckenfläche |  | 0 | 0 | NEW | 2.5 | AllplanAttributes - Bezeichnung: Gipsfaserplatten 2-lagig (BSK); RoomName: Nasszelle DZ
Gipsfaserplatten 2-lagig (BSK) | WUN-H2-E01-068a | CEILING | Installationshöhe 0.764 m | 1166Dfl0000033945/02 | m² | Trockenbauarbeiten | 2 | 0.764 | 0 | 1 | Bekleidung | Installationshöhe | 0 | 0 | NEW | 2.5 | AllplanAttributes - ash_lichte Raumhöhe: 2.500000; OKFF: 0; RoomName: Nasszelle DZ
Gipskarton, imprägniert | WUN-H2-E01-068a | CEILING | B 0.1 m | 1166Dfl0000033945/03 | m² | Trockenbauarbeiten | 3 | 0.1 | 0 | 1 | Bekleidung | B | 0 | 0 | NEW | 2.5 | AllplanAttributes - Bezeichnung: Gipskarton, imprägniert; ash_lichte Raumhöhe: 2.500000; OKFF: 0; RoomName: Nasszelle DZ; Pset_CoveringCommon - AcousticRating: -
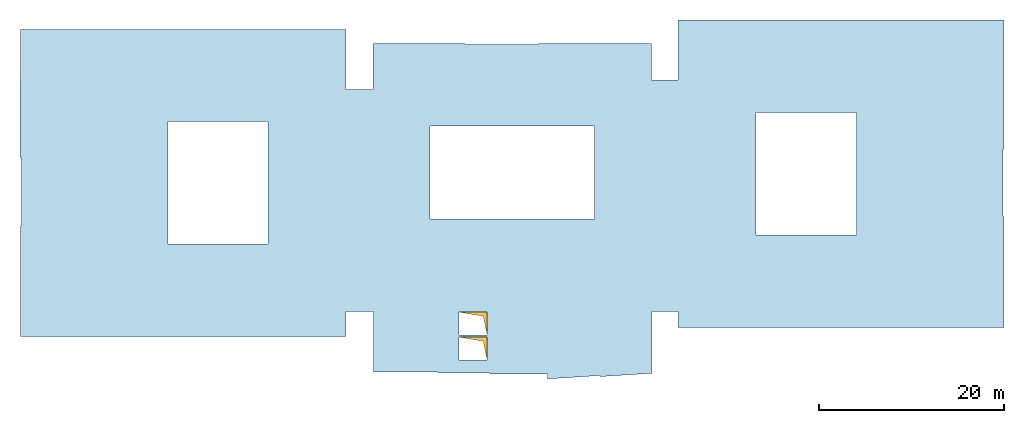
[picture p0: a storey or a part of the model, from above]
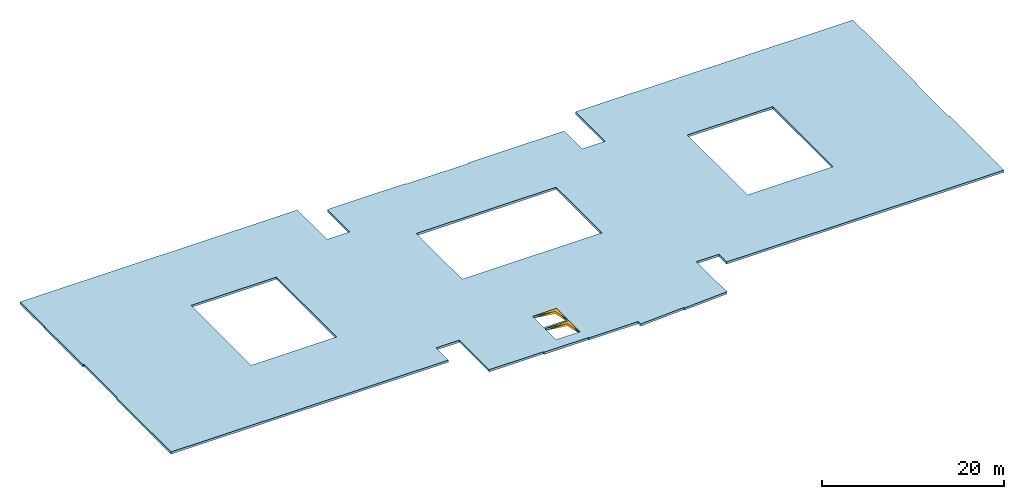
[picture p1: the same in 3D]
Properties of the parts of a building model (IFC4), part 14 of 80

# IfcCovering (3945)
Name | In | PredefinedType | Material | Allright_Bauteil_ID | Abrechnungsart | Gewerk | Schichtnummer | Schichtdicke (m) | Dicke (m) | Faktor | Objektname | AllplanAttributes, Material | Bezugshöhe | Deltahöhe | Status | D_lichte Raumhöhe [Zahl] (m)
Gipsfaserplatten 2-lagig (BSK) | WUN-H2-E01-068a | CEILING | D1 0.001 m | 1166Dfl0000033945/04 | m² | Maler- und Lackierarbeiten | 4 | 0.001 | 0 | 1 | Bekleidung | D1 | 0 | 0 | NEW | 2.5 | AllplanAttributes - ash_lichte Raumhöhe: 2.500000; OKFF: 0; RoomName: Nasszelle DZ
 | WUN-H2-E01-068a | CLADDING | 50 0.001 m | 1166Sfl0000665074/01 | m² | Maler- und Lackierarbeiten | 1 | 0.001 | 0 | 1 | Seitenfläche | 50 | 150 | 2500 | NEW
a-sh Wandbelag | WUN-H2-E01-068a | CLADDING | 68 0.01 m | 1166Sfl0000667028/01 | m² | Maler- und Lackierarbeiten | 1 | 0.01 | 0 | 1 | Seitenfläche | 68 | 100 | 3000 | NEW | AllplanAttributes - Bezeichnung: a-sh Wandbelag; Attributset-Objekt: Covering
Fliesen Mosaik | WUN-H2-E01-047a | FLOORING | Fl2 0.15 m | 1166Bfl0000490604/01 | m² | Bodenbelagsarbeiten | 1 | 0.15 | 0 | 1 | Bodenfläche | Fl2 | 0 | 0 | NEW | AllplanAttributes - Bezeichnung: Fliesen Mosaik; Raumnr. Bauherr: 2.11_A2_02; ash B_Aufbau: B11; ash B_Rutschhemmung: R10; ash B_Bewertungsgruppe Barfußbereich: B
Fliesen | WUN-H2-E01-047a | FLOORING | Fl1 0.15 m | 1166Bfl0000033772/01 | m² | Bodenbelagsarbeiten | 1 | 0.15 | 0 | 1 | Bodenfläche | Fl1 | 0 | 0 | NEW | AllplanAttributes - Bezeichnung: Fliesen; Raumnr. Bauherr: 2.11_A2_02; ash B_Aufbau: B10; ash B_Rutschhemmung: R10
Gipsfaserplatten 2-lagig (BSK) | WUN-H2-E01-047a | CEILING | layer 0.036 m | 1166Dfl0000033773/01 | m² | Trockenbauarbeiten | 1 | 0.036 | 0 | 1 | Deckenfläche |  | 0 | 0 | NEW | 2.5 | AllplanAttributes - Bezeichnung: Gipsfaserplatten 2-lagig (BSK); RoomName: Nasszelle DZ
Gipsfaserplatten 2-lagig (BSK) | WUN-H2-E01-047a | CEILING | Installationshöhe 0.764 m | 1166Dfl0000033773/02 | m² | Trockenbauarbeiten | 2 | 0.764 | 0 | 1 | Bekleidung | Installationshöhe | 0 | 0 | NEW | 2.5 | AllplanAttributes - ash_lichte Raumhöhe: 2.500000; OKFF: 0; RoomName: Nasszelle DZ
Gipskarton, imprägniert | WUN-H2-E01-047a | CEILING | B 0.1 m | 1166Dfl0000033773/03 | m² | Trockenbauarbeiten | 3 | 0.1 | 0 | 1 | Bekleidung | B | 0 | 0 | NEW | 2.5 | AllplanAttributes - Bezeichnung: Gipskarton, imprägniert; ash_lichte Raumhöhe: 2.500000; OKFF: 0; RoomName: Nasszelle DZ; Pset_CoveringCommon - AcousticRating: -
Gipsfaserplatten 2-lagig (BSK) | WUN-H2-E01-047a | CEILING | D1 0.001 m | 1166Dfl0000033773/04 | m² | Maler- und Lackierarbeiten | 4 | 0.001 | 0 | 1 | Bekleidung | D1 | 0 | 0 | NEW | 2.5 | AllplanAttributes - ash_lichte Raumhöhe: 2.500000; OKFF: 0; RoomName: Nasszelle DZ
 | WUN-H2-E01-047a | CLADDING | 50 0.001 m | 1166Sfl0000665075/01 | m² | Maler- und Lackierarbeiten | 1 | 0.001 | 0 | 1 | Seitenfläche | 50 | 150 | 2500 | NEW
a-sh Wandbelag | WUN-H2-E01-047a | CLADDING | 68 0.01 m | 1166Sfl0000665359/01 | m² | Maler- und Lackierarbeiten | 1 | 0.01 | 0 | 1 | Seitenfläche | 68 | 100 | 3000 | NEW | AllplanAttributes - Bezeichnung: a-sh Wandbelag; Attributset-Objekt: Covering
Fliesen Mosaik | WUN-H2-E01-046a | FLOORING | Fl2 0.15 m | 1166Bfl0000490404/01 | m² | Bodenbelagsarbeiten | 1 | 0.15 | 0 | 1 | Bodenfläche | Fl2 | 0 | 0 | NEW | AllplanAttributes - Bezeichnung: Fliesen Mosaik; Raumnr. Bauherr: 2.11_A2_02; ash B_Aufbau: B11; ash B_Rutschhemmung: R10; ash B_Bewertungsgruppe Barfußbereich: B
Fliesen | WUN-H2-E01-046a | FLOORING | Fl1 0.15 m | 1166Bfl0000033761/01 | m² | Bodenbelagsarbeiten | 1 | 0.15 | 0 | 1 | Bodenfläche | Fl1 | 0 | 0 | NEW | AllplanAttributes - Bezeichnung: Fliesen; Raumnr. Bauherr: 2.11_A2_02; ash B_Aufbau: B10; ash B_Rutschhemmung: R10
Gipsfaserplatten 2-lagig (BSK) | WUN-H2-E01-046a | CEILING | layer 0.036 m | 1166Dfl0000033762/01 | m² | Trockenbauarbeiten | 1 | 0.036 | 0 | 1 | Deckenfläche |  | 0 | 0 | NEW | 2.5 | AllplanAttributes - Bezeichnung: Gipsfaserplatten 2-lagig (BSK); RoomName: Nasszelle DZ
Gipsfaserplatten 2-lagig (BSK) | WUN-H2-E01-046a | CEILING | Installationshöhe 0.764 m | 1166Dfl0000033762/02 | m² | Trockenbauarbeiten | 2 | 0.764 | 0 | 1 | Bekleidung | Installationshöhe | 0 | 0 | NEW | 2.5 | AllplanAttributes - ash_lichte Raumhöhe: 2.500000; OKFF: 0; RoomName: Nasszelle DZ
Gipskarton, imprägniert | WUN-H2-E01-046a | CEILING | B 0.1 m | 1166Dfl0000033762/03 | m² | Trockenbauarbeiten | 3 | 0.1 | 0 | 1 | Bekleidung | B | 0 | 0 | NEW | 2.5 | AllplanAttributes - Bezeichnung: Gipskarton, imprägniert; ash_lichte Raumhöhe: 2.500000; OKFF: 0; RoomName: Nasszelle DZ; Pset_CoveringCommon - AcousticRating: -
Gipsfaserplatten 2-lagig (BSK) | WUN-H2-E01-046a | CEILING | D1 0.001 m | 1166Dfl0000033762/04 | m² | Maler- und Lackierarbeiten | 4 | 0.001 | 0 | 1 | Bekleidung | D1 | 0 | 0 | NEW | 2.5 | AllplanAttributes - ash_lichte Raumhöhe: 2.500000; OKFF: 0; RoomName: Nasszelle DZ
 | WUN-H2-E01-046a | CLADDING | 50 0.001 m | 1166Sfl0000665076/01 | m² | Maler- und Lackierarbeiten | 1 | 0.001 | 0 | 1 | Seitenfläche | 50 | 150 | 2500 | NEW
a-sh Wandbelag | WUN-H2-E01-046a | CLADDING | 68 0.01 m | 1166Sfl0000665290/01 | m² | Maler- und Lackierarbeiten | 1 | 0.01 | 0 | 1 | Seitenfläche | 68 | 100 | 3000 | NEW | AllplanAttributes - Bezeichnung: a-sh Wandbelag; Attributset-Objekt: Covering
Fliesen Mosaik | WUN-H2-E01-045a | FLOORING | Fl2 0.15 m | 1166Bfl0000490204/01 | m² | Bodenbelagsarbeiten | 1 | 0.15 | 0 | 1 | Bodenfläche | Fl2 | 0 | 0 | NEW | AllplanAttributes - Bezeichnung: Fliesen Mosaik; Raumnr. Bauherr: 2.11_A2_02; ash B_Aufbau: B11; ash B_Rutschhemmung: R10; ash B_Bewertungsgruppe Barfußbereich: B
Fliesen | WUN-H2-E01-045a | FLOORING | Fl1 0.15 m | 1166Bfl0000033750/01 | m² | Bodenbelagsarbeiten | 1 | 0.15 | 0 | 1 | Bodenfläche | Fl1 | 0 | 0 | NEW | AllplanAttributes - Bezeichnung: Fliesen; Raumnr. Bauherr: 2.11_A2_02; ash B_Aufbau: B10; ash B_Rutschhemmung: R10
Gipsfaserplatten 2-lagig (BSK) | WUN-H2-E01-045a | CEILING | layer 0.036 m | 1166Dfl0000033751/01 | m² | Trockenbauarbeiten | 1 | 0.036 | 0 | 1 | Deckenfläche |  | 0 | 0 | NEW | 2.5 | AllplanAttributes - Bezeichnung: Gipsfaserplatten 2-lagig (BSK); RoomName: Nasszelle DZ
Gipsfaserplatten 2-lagig (BSK) | WUN-H2-E01-045a | CEILING | Installationshöhe 0.764 m | 1166Dfl0000033751/02 | m² | Trockenbauarbeiten | 2 | 0.764 | 0 | 1 | Bekleidung | Installationshöhe | 0 | 0 | NEW | 2.5 | AllplanAttributes - ash_lichte Raumhöhe: 2.500000; OKFF: 0; RoomName: Nasszelle DZ
Gipskarton, imprägniert | WUN-H2-E01-045a | CEILING | B 0.1 m | 1166Dfl0000033751/03 | m² | Trockenbauarbeiten | 3 | 0.1 | 0 | 1 | Bekleidung | B | 0 | 0 | NEW | 2.5 | AllplanAttributes - Bezeichnung: Gipskarton, imprägniert; ash_lichte Raumhöhe: 2.500000; OKFF: 0; RoomName: Nasszelle DZ; Pset_CoveringCommon - AcousticRating: -
Gipsfaserplatten 2-lagig (BSK) | WUN-H2-E01-045a | CEILING | D1 0.001 m | 1166Dfl0000033751/04 | m² | Maler- und Lackierarbeiten | 4 | 0.001 | 0 | 1 | Bekleidung | D1 | 0 | 0 | NEW | 2.5 | AllplanAttributes - ash_lichte Raumhöhe: 2.500000; OKFF: 0; RoomName: Nasszelle DZ
 | WUN-H2-E01-045a | CLADDING | 50 0.001 m | 1166Sfl0000665077/01 | m² | Maler- und Lackierarbeiten | 1 | 0.001 | 0 | 1 | Seitenfläche | 50 | 150 | 2500 | NEW
a-sh Wandbelag | WUN-H2-E01-045a | CLADDING | 68 0.01 m | 1166Sfl0000665221/01 | m² | Maler- und Lackierarbeiten | 1 | 0.01 | 0 | 1 | Seitenfläche | 68 | 100 | 3000 | NEW | AllplanAttributes - Bezeichnung: a-sh Wandbelag; Attributset-Objekt: Covering
Fliesen Mosaik | WUN-H2-E01-044a | FLOORING | Fl2 0.15 m | 1166Bfl0000490004/01 | m² | Bodenbelagsarbeiten | 1 | 0.15 | 0 | 1 | Bodenfläche | Fl2 | 0 | 0 | NEW | AllplanAttributes - Bezeichnung: Fliesen Mosaik; Raumnr. Bauherr: 2.11_A2_02; ash B_Aufbau: B11; ash B_Rutschhemmung: R10; ash B_Bewertungsgruppe Barfußbereich: B
Fliesen | WUN-H2-E01-044a | FLOORING | Fl1 0.15 m | 1166Bfl0000033739/01 | m² | Bodenbelagsarbeiten | 1 | 0.15 | 0 | 1 | Bodenfläche | Fl1 | 0 | 0 | NEW | AllplanAttributes - Bezeichnung: Fliesen; Raumnr. Bauherr: 2.11_A2_02; ash B_Aufbau: B10; ash B_Rutschhemmung: R10
Gipsfaserplatten 2-lagig (BSK) | WUN-H2-E01-044a | CEILING | layer 0.036 m | 1166Dfl0000033740/01 | m² | Trockenbauarbeiten | 1 | 0.036 | 0 | 1 | Deckenfläche |  | 0 | 0 | NEW | 2.5 | AllplanAttributes - Bezeichnung: Gipsfaserplatten 2-lagig (BSK); RoomName: Nasszelle DZ
Gipsfaserplatten 2-lagig (BSK) | WUN-H2-E01-044a | CEILING | Installationshöhe 0.764 m | 1166Dfl0000033740/02 | m² | Trockenbauarbeiten | 2 | 0.764 | 0 | 1 | Bekleidung | Installationshöhe | 0 | 0 | NEW | 2.5 | AllplanAttributes - ash_lichte Raumhöhe: 2.500000; OKFF: 0; RoomName: Nasszelle DZ
Gipskarton, imprägniert | WUN-H2-E01-044a | CEILING | B 0.1 m | 1166Dfl0000033740/03 | m² | Trockenbauarbeiten | 3 | 0.1 | 0 | 1 | Bekleidung | B | 0 | 0 | NEW | 2.5 | AllplanAttributes - Bezeichnung: Gipskarton, imprägniert; ash_lichte Raumhöhe: 2.500000; OKFF: 0; RoomName: Nasszelle DZ; Pset_CoveringCommon - AcousticRating: -
Gipsfaserplatten 2-lagig (BSK) | WUN-H2-E01-044a | CEILING | D1 0.001 m | 1166Dfl0000033740/04 | m² | Maler- und Lackierarbeiten | 4 | 0.001 | 0 | 1 | Bekleidung | D1 | 0 | 0 | NEW | 2.5 | AllplanAttributes - ash_lichte Raumhöhe: 2.500000; OKFF: 0; RoomName: Nasszelle DZ
 | WUN-H2-E01-044a | CLADDING | 50 0.001 m | 1166Sfl0000665078/01 | m² | Maler- und Lackierarbeiten | 1 | 0.001 | 0 | 1 | Seitenfläche | 50 | 150 | 2500 | NEW
a-sh Wandbelag | WUN-H2-E01-044a | CLADDING | 68 0.01 m | 1166Sfl0000665152/01 | m² | Maler- und Lackierarbeiten | 1 | 0.01 | 0 | 1 | Seitenfläche | 68 | 100 | 3000 | NEW | AllplanAttributes - Bezeichnung: a-sh Wandbelag; Attributset-Objekt: Covering
Fliesen Mosaik | WUN-H2-E01-043a | FLOORING | Fl2 0.15 m | 1166Bfl0000489804/01 | m² | Bodenbelagsarbeiten | 1 | 0.15 | 0 | 1 | Bodenfläche | Fl2 | 0 | 0 | NEW | AllplanAttributes - Bezeichnung: Fliesen Mosaik; Raumnr. Bauherr: 2.11_A2_02; ash B_Aufbau: B11; ash B_Rutschhemmung: R10; ash B_Bewertungsgruppe Barfußbereich: B
Fliesen | WUN-H2-E01-043a | FLOORING | Fl1 0.15 m | 1166Bfl0000033728/01 | m² | Bodenbelagsarbeiten | 1 | 0.15 | 0 | 1 | Bodenfläche | Fl1 | 0 | 0 | NEW | AllplanAttributes - Bezeichnung: Fliesen; Raumnr. Bauherr: 2.11_A2_02; ash B_Aufbau: B10; ash B_Rutschhemmung: R10
Gipsfaserplatten 2-lagig (BSK) | WUN-H2-E01-043a | CEILING | layer 0.036 m | 1166Dfl0000033729/01 | m² | Trockenbauarbeiten | 1 | 0.036 | 0 | 1 | Deckenfläche |  | 0 | 0 | NEW | 2.5 | AllplanAttributes - Bezeichnung: Gipsfaserplatten 2-lagig (BSK); RoomName: Nasszelle DZ
Gipsfaserplatten 2-lagig (BSK) | WUN-H2-E01-043a | CEILING | Installationshöhe 0.764 m | 1166Dfl0000033729/02 | m² | Trockenbauarbeiten | 2 | 0.764 | 0 | 1 | Bekleidung | Installationshöhe | 0 | 0 | NEW | 2.5 | AllplanAttributes - ash_lichte Raumhöhe: 2.500000; OKFF: 0; RoomName: Nasszelle DZ
Gipskarton, imprägniert | WUN-H2-E01-043a | CEILING | B 0.1 m | 1166Dfl0000033729/03 | m² | Trockenbauarbeiten | 3 | 0.1 | 0 | 1 | Bekleidung | B | 0 | 0 | NEW | 2.5 | AllplanAttributes - Bezeichnung: Gipskarton, imprägniert; ash_lichte Raumhöhe: 2.500000; OKFF: 0; RoomName: Nasszelle DZ; Pset_CoveringCommon - AcousticRating: -
Gipsfaserplatten 2-lagig (BSK) | WUN-H2-E01-043a | CEILING | D1 0.001 m | 1166Dfl0000033729/04 | m² | Maler- und Lackierarbeiten | 4 | 0.001 | 0 | 1 | Bekleidung | D1 | 0 | 0 | NEW | 2.5 | AllplanAttributes - ash_lichte Raumhöhe: 2.500000; OKFF: 0; RoomName: Nasszelle DZ
 | WUN-H2-E01-043a | CLADDING | 50 0.001 m | 1166Sfl0000665079/01 | m² | Maler- und Lackierarbeiten | 1 | 0.001 | 0 | 1 | Seitenfläche | 50 | 150 | 2500 | NEW
a-sh Wandbelag | WUN-H2-E01-043a | CLADDING | 68 0.01 m | 1166Sfl0000665083/01 | m² | Maler- und Lackierarbeiten | 1 | 0.01 | 0 | 1 | Seitenfläche | 68 | 100 | 3000 | NEW | AllplanAttributes - Bezeichnung: a-sh Wandbelag; Attributset-Objekt: Covering
Fliesen Mosaik | WUN-H2-E01-019a | FLOORING | Fl2 0.15 m | 1166Bfl0000489204/01 | m² | Bodenbelagsarbeiten | 1 | 0.15 | 0 | 1 | Bodenfläche | Fl2 | 0 | 0 | NEW | AllplanAttributes - Bezeichnung: Fliesen Mosaik; Raumnr. Bauherr: 2.11_A2_02; ash B_Aufbau: B11; ash B_Rutschhemmung: R10; ash B_Bewertungsgruppe Barfußbereich: B
Fliesen | WUN-H2-E01-019a | FLOORING | Fl1 0.15 m | 1166Bfl0000033629/01 | m² | Bodenbelagsarbeiten | 1 | 0.15 | 0 | 1 | Bodenfläche | Fl1 | 0 | 0 | NEW | AllplanAttributes - Bezeichnung: Fliesen; Raumnr. Bauherr: 2.11_A2_02; ash B_Aufbau: B10; ash B_Rutschhemmung: R10
Gipsfaserplatten 2-lagig (BSK) | WUN-H2-E01-019a | CEILING | layer 0.036 m | 1166Dfl0000033630/01 | m² | Trockenbauarbeiten | 1 | 0.036 | 0 | 1 | Deckenfläche |  | 0 | 0 | NEW | 2.5 | AllplanAttributes - Bezeichnung: Gipsfaserplatten 2-lagig (BSK); RoomName: Nasszelle DZ
Gipsfaserplatten 2-lagig (BSK) | WUN-H2-E01-019a | CEILING | Installationshöhe 0.764 m | 1166Dfl0000033630/02 | m² | Trockenbauarbeiten | 2 | 0.764 | 0 | 1 | Bekleidung | Installationshöhe | 0 | 0 | NEW | 2.5 | AllplanAttributes - ash_lichte Raumhöhe: 2.500000; OKFF: 0; RoomName: Nasszelle DZ
Gipskarton, imprägniert | WUN-H2-E01-019a | CEILING | B 0.1 m | 1166Dfl0000033630/03 | m² | Trockenbauarbeiten | 3 | 0.1 | 0 | 1 | Bekleidung | B | 0 | 0 | NEW | 2.5 | AllplanAttributes - Bezeichnung: Gipskarton, imprägniert; ash_lichte Raumhöhe: 2.500000; OKFF: 0; RoomName: Nasszelle DZ; Pset_CoveringCommon - AcousticRating: -
Gipsfaserplatten 2-lagig (BSK) | WUN-H2-E01-019a | CEILING | D1 0.001 m | 1166Dfl0000033630/04 | m² | Maler- und Lackierarbeiten | 4 | 0.001 | 0 | 1 | Bekleidung | D1 | 0 | 0 | NEW | 2.5 | AllplanAttributes - ash_lichte Raumhöhe: 2.500000; OKFF: 0; RoomName: Nasszelle DZ
 | WUN-H2-E01-019a | CLADDING | 50 0.001 m | 1166Sfl0000665080/01 | m² | Maler- und Lackierarbeiten | 1 | 0.001 | 0 | 1 | Seitenfläche | 50 | 150 | 2500 | NEW
a-sh Wandbelag | WUN-H2-E01-019a | CLADDING | 68 0.01 m | 1166Sfl0000666283/01 | m² | Maler- und Lackierarbeiten | 1 | 0.01 | 0 | 1 | Seitenfläche | 68 | 100 | 3000 | NEW | AllplanAttributes - Bezeichnung: a-sh Wandbelag; Attributset-Objekt: Covering
Fliesen Mosaik | WUN-H2-E01-096a | FLOORING | Fl2 0.15 m | 1166Bfl0000490817/01 | m² | Bodenbelagsarbeiten | 1 | 0.15 | 0 | 1 | Bodenfläche | Fl2 | 0 | 0 | NEW | AllplanAttributes - Bezeichnung: Fliesen Mosaik; Raumnr. Bauherr: 2.11_A2_02; ash B_Aufbau: B11; ash B_Rutschhemmung: R10; ash B_Bewertungsgruppe Barfußbereich: B
Fliesen | WUN-H2-E01-096a | FLOORING | Fl1 0.15 m | 1166Bfl0000034549/01 | m² | Bodenbelagsarbeiten | 1 | 0.15 | 0 | 1 | Bodenfläche | Fl1 | 0 | 0 | NEW | AllplanAttributes - Bezeichnung: Fliesen; Raumnr. Bauherr: 2.11_A2_02; ash B_Aufbau: B10; ash B_Rutschhemmung: R10
Gipsfaserplatten 2-lagig (BSK) | WUN-H2-E01-096a | CEILING | layer 0.036 m | 1166Dfl0000034550/01 | m² | Trockenbauarbeiten | 1 | 0.036 | 0 | 1 | Deckenfläche |  | 0 | 0 | NEW | 2.5 | AllplanAttributes - Bezeichnung: Gipsfaserplatten 2-lagig (BSK); RoomName: Nasszelle DZ
Gipsfaserplatten 2-lagig (BSK) | WUN-H2-E01-096a | CEILING | Installationshöhe 0.764 m | 1166Dfl0000034550/02 | m² | Trockenbauarbeiten | 2 | 0.764 | 0 | 1 | Bekleidung | Installationshöhe | 0 | 0 | NEW | 2.5 | AllplanAttributes - ash_lichte Raumhöhe: 2.500000; OKFF: 0; RoomName: Nasszelle DZ
Gipskarton, imprägniert | WUN-H2-E01-096a | CEILING | B 0.1 m | 1166Dfl0000034550/03 | m² | Trockenbauarbeiten | 3 | 0.1 | 0 | 1 | Bekleidung | B | 0 | 0 | NEW | 2.5 | AllplanAttributes - Bezeichnung: Gipskarton, imprägniert; ash_lichte Raumhöhe: 2.500000; OKFF: 0; RoomName: Nasszelle DZ; Pset_CoveringCommon - AcousticRating: -
Gipsfaserplatten 2-lagig (BSK) | WUN-H2-E01-096a | CEILING | D1 0.001 m | 1166Dfl0000034550/04 | m² | Maler- und Lackierarbeiten | 4 | 0.001 | 0 | 1 | Bekleidung | D1 | 0 | 0 | NEW | 2.5 | AllplanAttributes - ash_lichte Raumhöhe: 2.500000; OKFF: 0; RoomName: Nasszelle DZ
 | WUN-H2-E01-096a | CLADDING | 50 0.001 m | 1166Sfl0000665081/01 | m² | Maler- und Lackierarbeiten | 1 | 0.001 | 0 | 1 | Seitenfläche | 50 | 150 | 2500 | NEW
a-sh Wandbelag | WUN-H2-E01-096a | CLADDING | 68 0.01 m | 1166Sfl0000666670/01 | m² | Maler- und Lackierarbeiten | 1 | 0.01 | 0 | 1 | Seitenfläche | 68 | 100 | 3000 | NEW | AllplanAttributes - Bezeichnung: a-sh Wandbelag; Attributset-Objekt: Covering
Fliesen Mosaik | WUN-H2-E01-042a | FLOORING | Fl2 0.15 m | 1166Bfl0000489604/01 | m² | Bodenbelagsarbeiten | 1 | 0.15 | 0 | 1 | Bodenfläche | Fl2 | 0 | 0 | NEW | AllplanAttributes - Bezeichnung: Fliesen Mosaik; Raumnr. Bauherr: 2.11_A2_02; ash B_Aufbau: B11; ash B_Rutschhemmung: R10; ash B_Bewertungsgruppe Barfußbereich: B
a-sh Wandbelag | WUN-H2-E01-042a | CLADDING | 68 0.01 m | 1166Sfl0000664961/01 | m² | Maler- und Lackierarbeiten | 1 | 0.01 | 0 | 1 | Seitenfläche | 68 | 100 | 3000 | NEW | AllplanAttributes - Bezeichnung: a-sh Wandbelag; Attributset-Objekt: Covering
Fliesen | WUN-H2-E01-042a | FLOORING | Fl1 0.15 m | 1166Bfl0000033717/01 | m² | Bodenbelagsarbeiten | 1 | 0.15 | 0 | 1 | Bodenfläche | Fl1 | 0 | 0 | NEW | AllplanAttributes - Bezeichnung: Fliesen; Raumnr. Bauherr: 2.11_A2_02; ash B_Aufbau: B10; ash B_Rutschhemmung: R10
 | WUN-H2-E01-042a | CLADDING | 50 0.001 m | 1166Sfl0000664511/01 | m² | Maler- und Lackierarbeiten | 1 | 0.001 | 0 | 1 | Seitenfläche | 50 | 150 | 2500 | NEW
Gipsfaserplatten 2-lagig (BSK) | WUN-H2-E01-042a | CEILING | layer 0.036 m | 1166Dfl0000033718/01 | m² | Trockenbauarbeiten | 1 | 0.036 | 0 | 1 | Deckenfläche |  | 0 | 0 | NEW | 2.5 | AllplanAttributes - Bezeichnung: Gipsfaserplatten 2-lagig (BSK); RoomName: Nasszelle DZ
Gipsfaserplatten 2-lagig (BSK) | WUN-H2-E01-042a | CEILING | Installationshöhe 0.764 m | 1166Dfl0000033718/02 | m² | Trockenbauarbeiten | 2 | 0.764 | 0 | 1 | Bekleidung | Installationshöhe | 0 | 0 | NEW | 2.5 | AllplanAttributes - ash_lichte Raumhöhe: 2.500000; OKFF: 0; RoomName: Nasszelle DZ
Gipskarton, imprägniert | WUN-H2-E01-042a | CEILING | B 0.1 m | 1166Dfl0000033718/03 | m² | Trockenbauarbeiten | 3 | 0.1 | 0 | 1 | Bekleidung | B | 0 | 0 | NEW | 2.5 | AllplanAttributes - Bezeichnung: Gipskarton, imprägniert; ash_lichte Raumhöhe: 2.500000; OKFF: 0; RoomName: Nasszelle DZ; Pset_CoveringCommon - AcousticRating: -
Gipsfaserplatten 2-lagig (BSK) | WUN-H2-E01-042a | CEILING | D1 0.001 m | 1166Dfl0000033718/04 | m² | Maler- und Lackierarbeiten | 4 | 0.001 | 0 | 1 | Bekleidung | D1 | 0 | 0 | NEW | 2.5 | AllplanAttributes - ash_lichte Raumhöhe: 2.500000; OKFF: 0; RoomName: Nasszelle DZ
Fliesen Mosaik | WUN-H2-E01-091a | FLOORING | Fl2 0.15 m | 1166Bfl0000491817/01 | m² | Bodenbelagsarbeiten | 1 | 0.15 | 0 | 1 | Bodenfläche | Fl2 | 0 | 0 | NEW | AllplanAttributes - Bezeichnung: Fliesen Mosaik; Raumnr. Bauherr: 2.11_A2_02; ash B_Aufbau: B11; ash B_Rutschhemmung: R10; ash B_Bewertungsgruppe Barfußbereich: B
Fliesen | WUN-H2-E01-091a | FLOORING | Fl1 0.15 m | 1166Bfl0000034455/01 | m² | Bodenbelagsarbeiten | 1 | 0.15 | 0 | 1 | Bodenfläche | Fl1 | 0 | 0 | NEW | AllplanAttributes - Bezeichnung: Fliesen; Raumnr. Bauherr: 2.11_A2_02; ash B_Aufbau: B10; ash B_Rutschhemmung: R10
Gipsfaserplatten 2-lagig (BSK) | WUN-H2-E01-091a | CEILING | layer 0.036 m | 1166Dfl0000034456/01 | m² | Trockenbauarbeiten | 1 | 0.036 | 0 | 1 | Deckenfläche |  | 0 | 0 | NEW | 2.5 | AllplanAttributes - Bezeichnung: Gipsfaserplatten 2-lagig (BSK); RoomName: Nasszelle DZ
Gipsfaserplatten 2-lagig (BSK) | WUN-H2-E01-091a | CEILING | Installationshöhe 0.764 m | 1166Dfl0000034456/02 | m² | Trockenbauarbeiten | 2 | 0.764 | 0 | 1 | Bekleidung | Installationshöhe | 0 | 0 | NEW | 2.5 | AllplanAttributes - ash_lichte Raumhöhe: 2.500000; OKFF: 0; RoomName: Nasszelle DZ
Gipskarton, imprägniert | WUN-H2-E01-091a | CEILING | B 0.1 m | 1166Dfl0000034456/03 | m² | Trockenbauarbeiten | 3 | 0.1 | 0 | 1 | Bekleidung | B | 0 | 0 | NEW | 2.5 | AllplanAttributes - Bezeichnung: Gipskarton, imprägniert; ash_lichte Raumhöhe: 2.500000; OKFF: 0; RoomName: Nasszelle DZ; Pset_CoveringCommon - AcousticRating: -
Gipsfaserplatten 2-lagig (BSK) | WUN-H2-E01-091a | CEILING | D1 0.001 m | 1166Dfl0000034456/04 | m² | Maler- und Lackierarbeiten | 4 | 0.001 | 0 | 1 | Bekleidung | D1 | 0 | 0 | NEW | 2.5 | AllplanAttributes - ash_lichte Raumhöhe: 2.500000; OKFF: 0; RoomName: Nasszelle DZ
 | WUN-H2-E01-091a | CLADDING | 50 0.001 m | 1166Sfl0000665082/01 | m² | Maler- und Lackierarbeiten | 1 | 0.001 | 0 | 1 | Seitenfläche | 50 | 150 | 2500 | NEW
a-sh Wandbelag | WUN-H2-E01-091a | CLADDING | 68 0.01 m | 1166Sfl0000666819/01 | m² | Maler- und Lackierarbeiten | 1 | 0.01 | 0 | 1 | Seitenfläche | 68 | 100 | 3000 | NEW | AllplanAttributes - Bezeichnung: a-sh Wandbelag; Attributset-Objekt: Covering
Gipsfaserplatten 2-lagig (BSK) | WUN-H2-E01-036 | CEILING | layer 0.036 m | 1166Dfl0000033501/01 | m² | Trockenbauarbeiten | 1 | 0.036 | 0 | 1 | Deckenfläche |  | 0 | 0 | NEW | 2.5 | AllplanAttributes - Bezeichnung: Gipsfaserplatten 2-lagig (BSK); RoomName: Sprechzimmer
Gipsfaserplatten 2-lagig (BSK) | WUN-H2-E01-036 | CEILING | Installationshöhe 0.714 m | 1166Dfl0000033501/02 | m² | Trockenbauarbeiten | 2 | 0.714 | 0 | 1 | Bekleidung | Installationshöhe | 0 | 0 | NEW | 2.5 | AllplanAttributes - ash_lichte Raumhöhe: 2.500000; OKFF: 0; RoomName: Sprechzimmer
Gipsfaserplatten 2-lagig (BSK) | WUN-H2-E01-036 | CEILING | A1 0.15 m | 1166Dfl0000033501/03 | m² | Trockenbauarbeiten | 3 | 0.15 | 0 | 1 | Bekleidung | A1 | 0 | 0 | NEW | 2.5 | AllplanAttributes - ash_lichte Raumhöhe: 2.500000; OKFF: 0; RoomName: Sprechzimmer; Pset_CoveringCommon - AcousticRating: -
Gipsfaserplatten 2-lagig (BSK) | WUN-H2-E01-036 | CEILING | D1 0.001 m | 1166Dfl0000033501/04 | m² | Maler- und Lackierarbeiten | 4 | 0.001 | 0 | 1 | Bekleidung | D1 | 0 | 0 | NEW | 2.5 | AllplanAttributes - ash_lichte Raumhöhe: 2.500000; OKFF: 0; RoomName: Sprechzimmer
Gipsfaserplatten 2-lagig (BSK) | WUN-H2-E01-036 | CEILING | layer 0.036 m | 1166Dfl0000222171/01 | m² | Trockenbauarbeiten | 1 | 0.036 | 0 | 1 | Deckenfläche |  | 0 | 0 | NEW | 2.5 | AllplanAttributes - Bezeichnung: Gipsfaserplatten 2-lagig (BSK); RoomName: Sprechzimmer
Gipsfaserplatten 2-lagig (BSK) | WUN-H2-E01-036 | CEILING | Installationshöhe 0.714 m | 1166Dfl0000222171/02 | m² | Trockenbauarbeiten | 2 | 0.714 | 0 | 1 | Bekleidung | Installationshöhe | 0 | 0 | NEW | 2.5 | AllplanAttributes - ash_lichte Raumhöhe: 2.500000; OKFF: 0; RoomName: Sprechzimmer
Gipsfaserplatten 2-lagig (BSK) | WUN-H2-E01-036 | CEILING | Aa 0.15 m | 1166Dfl0000222171/03 | m² | Trockenbauarbeiten | 3 | 0.15 | 0 | 1 | Bekleidung | Aa | 0 | 0 | NEW | 2.5 | AllplanAttributes - ash_lichte Raumhöhe: 2.500000; OKFF: 0; RoomName: Sprechzimmer; Pset_CoveringCommon - AcousticRating: -
Gipsfaserplatten 2-lagig (BSK) | WUN-H2-E01-036 | CEILING | D1 0.001 m | 1166Dfl0000222171/04 | m² | Maler- und Lackierarbeiten | 4 | 0.001 | 0 | 1 | Bekleidung | D1 | 0 | 0 | NEW | 2.5 | AllplanAttributes - ash_lichte Raumhöhe: 2.500000; OKFF: 0; RoomName: Sprechzimmer
PVC Bahnenware Holzoptik | WUN-H2-E01-036 | FLOORING | Ku1 0.15 m | 1166Bfl0000033490/01 | m² | Bodenbelagsarbeiten | 1 | 0.15 | 0 | 1 | Bodenfläche | Ku1 | 0 | 0 | NEW | AllplanAttributes - Bezeichnung: PVC Bahnenware Holzoptik; Raumnr. Bauherr: 2.11_A2_02; ash B_Aufbau: B9; ash B_Rutschhemmung: R9
 | WUN-H2-E01-036 | CLADDING | 49 0.001 m | 1166Sfl0000665716/01 | m² | Maler- und Lackierarbeiten | 1 | 0.001 | 0 | 1 | Seitenfläche | 49 | 150 | 3150 | NEW
Gipsfaserplatten 2-lagig (BSK) | WUN-H2-E01-035 | CEILING | layer 0.036 m | 1166Dfl0000221591/01 | m² | Trockenbauarbeiten | 1 | 0.036 | 0 | 1 | Deckenfläche |  | 0 | 0 | NEW | 2.5 | AllplanAttributes - Bezeichnung: Gipsfaserplatten 2-lagig (BSK); RoomName: Sprechzimmer
Gipsfaserplatten 2-lagig (BSK) | WUN-H2-E01-035 | CEILING | Installationshöhe 0.714 m | 1166Dfl0000221591/02 | m² | Trockenbauarbeiten | 2 | 0.714 | 0 | 1 | Bekleidung | Installationshöhe | 0 | 0 | NEW | 2.5 | AllplanAttributes - ash_lichte Raumhöhe: 2.500000; OKFF: 0; RoomName: Sprechzimmer
Gipsfaserplatten 2-lagig (BSK) | WUN-H2-E01-035 | CEILING | Aa 0.15 m | 1166Dfl0000221591/03 | m² | Trockenbauarbeiten | 3 | 0.15 | 0 | 1 | Bekleidung | Aa | 0 | 0 | NEW | 2.5 | AllplanAttributes - ash_lichte Raumhöhe: 2.500000; OKFF: 0; RoomName: Sprechzimmer; Pset_CoveringCommon - AcousticRating: -
Gipsfaserplatten 2-lagig (BSK) | WUN-H2-E01-035 | CEILING | D1 0.001 m | 1166Dfl0000221591/04 | m² | Maler- und Lackierarbeiten | 4 | 0.001 | 0 | 1 | Bekleidung | D1 | 0 | 0 | NEW | 2.5 | AllplanAttributes - ash_lichte Raumhöhe: 2.500000; OKFF: 0; RoomName: Sprechzimmer
Gipsfaserplatten 2-lagig (BSK) | WUN-H2-E01-035 | CEILING | layer 0.036 m | 1166Dfl0000034733/01 | m² | Trockenbauarbeiten | 1 | 0.036 | 0 | 1 | Deckenfläche |  | 0 | 0 | NEW | 2.5 | AllplanAttributes - Bezeichnung: Gipsfaserplatten 2-lagig (BSK); RoomName: Pause Personal
Gipsfaserplatten 2-lagig (BSK) | WUN-H2-E01-035 | CEILING | Installationshöhe 0.714 m | 1166Dfl0000034733/02 | m² | Trockenbauarbeiten | 2 | 0.714 | 0 | 1 | Bekleidung | Installationshöhe | 0 | 0 | NEW | 2.5 | AllplanAttributes - ash_lichte Raumhöhe: 2.500000; OKFF: 0; RoomName: Pause Personal
Gipsfaserplatten 2-lagig (BSK) | WUN-H2-E01-035 | CEILING | A1 0.15 m | 1166Dfl0000034733/03 | m² | Trockenbauarbeiten | 3 | 0.15 | 0 | 1 | Bekleidung | A1 | 0 | 0 | NEW | 2.5 | AllplanAttributes - ash_lichte Raumhöhe: 2.500000; OKFF: 0; RoomName: Pause Personal; Pset_CoveringCommon - AcousticRating: -
Gipsfaserplatten 2-lagig (BSK) | WUN-H2-E01-035 | CEILING | D1 0.001 m | 1166Dfl0000034733/04 | m² | Maler- und Lackierarbeiten | 4 | 0.001 | 0 | 1 | Bekleidung | D1 | 0 | 0 | NEW | 2.5 | AllplanAttributes - ash_lichte Raumhöhe: 2.500000; OKFF: 0; RoomName: Pause Personal
PVC Bahnenware Holzoptik | WUN-H2-E01-035 | FLOORING | Ku1 0.15 m | 1166Bfl0000034727/01 | m² | Bodenbelagsarbeiten | 1 | 0.15 | 0 | 1 | Bodenfläche | Ku1 | 0 | 0 | NEW | AllplanAttributes - Bezeichnung: PVC Bahnenware Holzoptik; Raumnr. Bauherr: 2.11_A2_02; ash B_Aufbau: B9; ash B_Rutschhemmung: R9
 | WUN-H2-E01-035 | CLADDING | 49 0.001 m | 1166Sfl0000665717/01 | m² | Maler- und Lackierarbeiten | 1 | 0.001 | 0 | 1 | Seitenfläche | 49 | 150 | 3150 | NEW
Gipsfaserplatten 2-lagig (BSK) | WUN-H2-E01-034 | CEILING | layer 0.036 m | 1166Dfl0000033488/01 | m² | Trockenbauarbeiten | 1 | 0.036 | 0 | 1 | Deckenfläche |  | 0 | 0 | NEW | 2.5 | AllplanAttributes - Bezeichnung: Gipsfaserplatten 2-lagig (BSK); RoomName: Sprechzimmer
Gipsfaserplatten 2-lagig (BSK) | WUN-H2-E01-034 | CEILING | Installationshöhe 0.714 m | 1166Dfl0000033488/02 | m² | Trockenbauarbeiten | 2 | 0.714 | 0 | 1 | Bekleidung | Installationshöhe | 0 | 0 | NEW | 2.5 | AllplanAttributes - ash_lichte Raumhöhe: 2.500000; OKFF: 0; RoomName: Sprechzimmer
Gipsfaserplatten 2-lagig (BSK) | WUN-H2-E01-034 | CEILING | A1 0.15 m | 1166Dfl0000033488/03 | m² | Trockenbauarbeiten | 3 | 0.15 | 0 | 1 | Bekleidung | A1 | 0 | 0 | NEW | 2.5 | AllplanAttributes - ash_lichte Raumhöhe: 2.500000; OKFF: 0; RoomName: Sprechzimmer; Pset_CoveringCommon - AcousticRating: -
Gipsfaserplatten 2-lagig (BSK) | WUN-H2-E01-034 | CEILING | D1 0.001 m | 1166Dfl0000033488/04 | m² | Maler- und Lackierarbeiten | 4 | 0.001 | 0 | 1 | Bekleidung | D1 | 0 | 0 | NEW | 2.5 | AllplanAttributes - ash_lichte Raumhöhe: 2.500000; OKFF: 0; RoomName: Sprechzimmer
Gipsfaserplatten 2-lagig (BSK) | WUN-H2-E01-034 | CEILING | layer 0.036 m | 1166Dfl0000221011/01 | m² | Trockenbauarbeiten | 1 | 0.036 | 0 | 1 | Deckenfläche |  | 0 | 0 | NEW | 2.5 | AllplanAttributes - Bezeichnung: Gipsfaserplatten 2-lagig (BSK); RoomName: Sprechzimmer
Gipsfaserplatten 2-lagig (BSK) | WUN-H2-E01-034 | CEILING | Installationshöhe 0.714 m | 1166Dfl0000221011/02 | m² | Trockenbauarbeiten | 2 | 0.714 | 0 | 1 | Bekleidung | Installationshöhe | 0 | 0 | NEW | 2.5 | AllplanAttributes - ash_lichte Raumhöhe: 2.500000; OKFF: 0; RoomName: Sprechzimmer
Gipsfaserplatten 2-lagig (BSK) | WUN-H2-E01-034 | CEILING | Aa 0.15 m | 1166Dfl0000221011/03 | m² | Trockenbauarbeiten | 3 | 0.15 | 0 | 1 | Bekleidung | Aa | 0 | 0 | NEW | 2.5 | AllplanAttributes - ash_lichte Raumhöhe: 2.500000; OKFF: 0; RoomName: Sprechzimmer; Pset_CoveringCommon - AcousticRating: -
Gipsfaserplatten 2-lagig (BSK) | WUN-H2-E01-034 | CEILING | D1 0.001 m | 1166Dfl0000221011/04 | m² | Maler- und Lackierarbeiten | 4 | 0.001 | 0 | 1 | Bekleidung | D1 | 0 | 0 | NEW | 2.5 | AllplanAttributes - ash_lichte Raumhöhe: 2.500000; OKFF: 0; RoomName: Sprechzimmer
PVC Bahnenware Holzoptik | WUN-H2-E01-034 | FLOORING | Ku1 0.15 m | 1166Bfl0000033477/01 | m² | Bodenbelagsarbeiten | 1 | 0.15 | 0 | 1 | Bodenfläche | Ku1 | 0 | 0 | NEW | AllplanAttributes - Bezeichnung: PVC Bahnenware Holzoptik; Raumnr. Bauherr: 2.11_A2_02; ash B_Aufbau: B9; ash B_Rutschhemmung: R9
 | WUN-H2-E01-034 | CLADDING | 49 0.001 m | 1166Sfl0000665718/01 | m² | Maler- und Lackierarbeiten | 1 | 0.001 | 0 | 1 | Seitenfläche | 49 | 150 | 3150 | NEW
Gipsfaserplatten 2-lagig (BSK) | WUN-H2-E01-033 | CEILING | layer 0.036 m | 1166Dfl0000220431/01 | m² | Trockenbauarbeiten | 1 | 0.036 | 0 | 1 | Deckenfläche |  | 0 | 0 | NEW | 2.5 | AllplanAttributes - Bezeichnung: Gipsfaserplatten 2-lagig (BSK); RoomName: Sprechzimmer
Gipsfaserplatten 2-lagig (BSK) | WUN-H2-E01-033 | CEILING | Installationshöhe 0.714 m | 1166Dfl0000220431/02 | m² | Trockenbauarbeiten | 2 | 0.714 | 0 | 1 | Bekleidung | Installationshöhe | 0 | 0 | NEW | 2.5 | AllplanAttributes - ash_lichte Raumhöhe: 2.500000; OKFF: 0; RoomName: Sprechzimmer
Gipsfaserplatten 2-lagig (BSK) | WUN-H2-E01-033 | CEILING | Aa 0.15 m | 1166Dfl0000220431/03 | m² | Trockenbauarbeiten | 3 | 0.15 | 0 | 1 | Bekleidung | Aa | 0 | 0 | NEW | 2.5 | AllplanAttributes - ash_lichte Raumhöhe: 2.500000; OKFF: 0; RoomName: Sprechzimmer; Pset_CoveringCommon - AcousticRating: -
Gipsfaserplatten 2-lagig (BSK) | WUN-H2-E01-033 | CEILING | D1 0.001 m | 1166Dfl0000220431/04 | m² | Maler- und Lackierarbeiten | 4 | 0.001 | 0 | 1 | Bekleidung | D1 | 0 | 0 | NEW | 2.5 | AllplanAttributes - ash_lichte Raumhöhe: 2.500000; OKFF: 0; RoomName: Sprechzimmer
Gipsfaserplatten 2-lagig (BSK) | WUN-H2-E01-033 | CEILING | layer 0.036 m | 1166Dfl0000033475/01 | m² | Trockenbauarbeiten | 1 | 0.036 | 0 | 1 | Deckenfläche |  | 0 | 0 | NEW | 2.5 | AllplanAttributes - Bezeichnung: Gipsfaserplatten 2-lagig (BSK); RoomName: Sprechzimmer
Gipsfaserplatten 2-lagig (BSK) | WUN-H2-E01-033 | CEILING | Installationshöhe 0.714 m | 1166Dfl0000033475/02 | m² | Trockenbauarbeiten | 2 | 0.714 | 0 | 1 | Bekleidung | Installationshöhe | 0 | 0 | NEW | 2.5 | AllplanAttributes - ash_lichte Raumhöhe: 2.500000; OKFF: 0; RoomName: Sprechzimmer
Gipsfaserplatten 2-lagig (BSK) | WUN-H2-E01-033 | CEILING | A1 0.15 m | 1166Dfl0000033475/03 | m² | Trockenbauarbeiten | 3 | 0.15 | 0 | 1 | Bekleidung | A1 | 0 | 0 | NEW | 2.5 | AllplanAttributes - ash_lichte Raumhöhe: 2.500000; OKFF: 0; RoomName: Sprechzimmer; Pset_CoveringCommon - AcousticRating: -
Gipsfaserplatten 2-lagig (BSK) | WUN-H2-E01-033 | CEILING | D1 0.001 m | 1166Dfl0000033475/04 | m² | Maler- und Lackierarbeiten | 4 | 0.001 | 0 | 1 | Bekleidung | D1 | 0 | 0 | NEW | 2.5 | AllplanAttributes - ash_lichte Raumhöhe: 2.500000; OKFF: 0; RoomName: Sprechzimmer
PVC Bahnenware Holzoptik | WUN-H2-E01-033 | FLOORING | Ku1 0.15 m | 1166Bfl0000033464/01 | m² | Bodenbelagsarbeiten | 1 | 0.15 | 0 | 1 | Bodenfläche | Ku1 | 0 | 0 | NEW | AllplanAttributes - Bezeichnung: PVC Bahnenware Holzoptik; Raumnr. Bauherr: 2.11_A2_02; ash B_Aufbau: B9; ash B_Rutschhemmung: R9
 | WUN-H2-E01-033 | CLADDING | 49 0.001 m | 1166Sfl0000665719/01 | m² | Maler- und Lackierarbeiten | 1 | 0.001 | 0 | 1 | Seitenfläche | 49 | 150 | 3150 | NEW
Gipsfaserplatten 2-lagig (BSK) | WUN-H2-E01-037 | CEILING | layer 0.036 m | 1166Dfl0000033514/01 | m² | Trockenbauarbeiten | 1 | 0.036 | 0 | 1 | Deckenfläche |  | 0 | 0 | NEW | 2.5 | AllplanAttributes - Bezeichnung: Gipsfaserplatten 2-lagig (BSK); RoomName: Sprechzimmer
Gipsfaserplatten 2-lagig (BSK) | WUN-H2-E01-037 | CEILING | Installationshöhe 0.714 m | 1166Dfl0000033514/02 | m² | Trockenbauarbeiten | 2 | 0.714 | 0 | 1 | Bekleidung | Installationshöhe | 0 | 0 | NEW | 2.5 | AllplanAttributes - ash_lichte Raumhöhe: 2.500000; OKFF: 0; RoomName: Sprechzimmer
Gipsfaserplatten 2-lagig (BSK) | WUN-H2-E01-037 | CEILING | A1 0.15 m | 1166Dfl0000033514/03 | m² | Trockenbauarbeiten | 3 | 0.15 | 0 | 1 | Bekleidung | A1 | 0 | 0 | NEW | 2.5 | AllplanAttributes - ash_lichte Raumhöhe: 2.500000; OKFF: 0; RoomName: Sprechzimmer; Pset_CoveringCommon - AcousticRating: -
Gipsfaserplatten 2-lagig (BSK) | WUN-H2-E01-037 | CEILING | D1 0.001 m | 1166Dfl0000033514/04 | m² | Maler- und Lackierarbeiten | 4 | 0.001 | 0 | 1 | Bekleidung | D1 | 0 | 0 | NEW | 2.5 | AllplanAttributes - ash_lichte Raumhöhe: 2.500000; OKFF: 0; RoomName: Sprechzimmer
Gipsfaserplatten 2-lagig (BSK) | WUN-H2-E01-037 | CEILING | layer 0.036 m | 1166Dfl0000222751/01 | m² | Trockenbauarbeiten | 1 | 0.036 | 0 | 1 | Deckenfläche |  | 0 | 0 | NEW | 2.5 | AllplanAttributes - Bezeichnung: Gipsfaserplatten 2-lagig (BSK); RoomName: Sprechzimmer
Gipsfaserplatten 2-lagig (BSK) | WUN-H2-E01-037 | CEILING | Installationshöhe 0.714 m | 1166Dfl0000222751/02 | m² | Trockenbauarbeiten | 2 | 0.714 | 0 | 1 | Bekleidung | Installationshöhe | 0 | 0 | NEW | 2.5 | AllplanAttributes - ash_lichte Raumhöhe: 2.500000; OKFF: 0; RoomName: Sprechzimmer
Gipsfaserplatten 2-lagig (BSK) | WUN-H2-E01-037 | CEILING | Aa 0.15 m | 1166Dfl0000222751/03 | m² | Trockenbauarbeiten | 3 | 0.15 | 0 | 1 | Bekleidung | Aa | 0 | 0 | NEW | 2.5 | AllplanAttributes - ash_lichte Raumhöhe: 2.500000; OKFF: 0; RoomName: Sprechzimmer; Pset_CoveringCommon - AcousticRating: -
Gipsfaserplatten 2-lagig (BSK) | WUN-H2-E01-037 | CEILING | D1 0.001 m | 1166Dfl0000222751/04 | m² | Maler- und Lackierarbeiten | 4 | 0.001 | 0 | 1 | Bekleidung | D1 | 0 | 0 | NEW | 2.5 | AllplanAttributes - ash_lichte Raumhöhe: 2.500000; OKFF: 0; RoomName: Sprechzimmer
PVC Bahnenware Holzoptik | WUN-H2-E01-037 | FLOORING | Ku1 0.15 m | 1166Bfl0000033503/01 | m² | Bodenbelagsarbeiten | 1 | 0.15 | 0 | 1 | Bodenfläche | Ku1 | 0 | 0 | NEW | AllplanAttributes - Bezeichnung: PVC Bahnenware Holzoptik; Raumnr. Bauherr: 2.11_A2_02; ash B_Aufbau: B9; ash B_Rutschhemmung: R9
 | WUN-H2-E01-037 | CLADDING | 49 0.001 m | 1166Sfl0000665720/01 | m² | Maler- und Lackierarbeiten | 1 | 0.001 | 0 | 1 | Seitenfläche | 49 | 150 | 3150 | NEW
PVC | WUN-H2-E01-027 | FLOORING | Ku3 0.15 m | 1166Bfl0000033387/01 | m² | Bodenbelagsarbeiten | 1 | 0.15 | 0 | 1 | Bodenfläche | Ku3 | 0 | 0 | NEW | AllplanAttributes - Bezeichnung: PVC; Raumnr. Bauherr: 2.11_A2_02; ash B_Aufbau: B9; ash B_Rutschhemmung: R9
Gipsfaserplatten 2-lagig (BSK) | WUN-H2-E01-027 | CEILING | C/C 0.036 m | 1166Dfl0000033388/01 | m² | Trockenbauarbeiten | 1 | 0.036 | 0 | 1 | Deckenfläche | C/C | 0 | 0 | NEW | 3.364 | AllplanAttributes - Bezeichnung: Gipsfaserplatten 2-lagig (BSK); RoomName: SV
Gipsfaserplatten 2-lagig (BSK) | WUN-H2-E01-027 | CEILING | D4 0.001 m | 1166Dfl0000033388/02 | m² | Maler- und Lackierarbeiten | 2 | 0.001 | 0 | 1 | Deckenfläche | D4 | 0 | 0 | NEW
 | WUN-H2-E01-027 | CLADDING | 50 0.001 m | 1166Sfl0000665721/01 | m² | Maler- und Lackierarbeiten | 1 | 0.001 | 0 | 1 | Seitenfläche | 50 | 150 | 2500 | NEW
PVC | WUN-H2-E01-028 | FLOORING | Ku3 0.15 m | 1166Bfl0000033398/01 | m² | Bodenbelagsarbeiten | 1 | 0.15 | 0 | 1 | Bodenfläche | Ku3 | 0 | 0 | NEW | AllplanAttributes - Bezeichnung: PVC; Raumnr. Bauherr: 2.11_A2_02; ash B_Aufbau: B9; ash B_Rutschhemmung: R9
Gipsfaserplatten 2-lagig (BSK) | WUN-H2-E01-028 | CEILING | C/C 0.036 m | 1166Dfl0000033399/01 | m² | Trockenbauarbeiten | 1 | 0.036 | 0 | 1 | Deckenfläche | C/C | 0 | 0 | NEW | 3.364 | AllplanAttributes - Bezeichnung: Gipsfaserplatten 2-lagig (BSK); RoomName: SV
Gipsfaserplatten 2-lagig (BSK) | WUN-H2-E01-028 | CEILING | D4 0.001 m | 1166Dfl0000033399/02 | m² | Maler- und Lackierarbeiten | 2 | 0.001 | 0 | 1 | Deckenfläche | D4 | 0 | 0 | NEW
 | WUN-H2-E01-028 | CLADDING | 50 0.001 m | 1166Sfl0000665722/01 | m² | Maler- und Lackierarbeiten | 1 | 0.001 | 0 | 1 | Seitenfläche | 50 | 150 | 2500 | NEW
PVC Bahnenware Uni | WUN-H2-E01-040 | FLOORING | Ku2 0.15 m | 1166Bfl0000033527/01 | m² | Bodenbelagsarbeiten | 1 | 0.15 | 0 | 1 | Bodenfläche | Ku2 | 0 | 0 | NEW | AllplanAttributes - Bezeichnung: PVC Bahnenware Uni; Raumnr. Bauherr: 2.11_A2_02; ash B_Aufbau: B9; ash B_Rutschhemmung: R9
Gipsfaserplatten 2-lagig (BSK) | WUN-H2-E01-040 | CEILING | layer 0.036 m | 1166Dfl0000033528/01 | m² | Trockenbauarbeiten | 1 | 0.036 | 0 | 1 | Deckenfläche |  | 0 | 0 | NEW | 2.5 | AllplanAttributes - Bezeichnung: Gipsfaserplatten 2-lagig (BSK); RoomName: Geräte
Gipsfaserplatten 2-lagig (BSK) | WUN-H2-E01-040 | CEILING | Installationshöhe 0.764 m | 1166Dfl0000033528/02 | m² | Trockenbauarbeiten | 2 | 0.764 | 0 | 1 | Bekleidung | Installationshöhe | 0 | 0 | NEW | 2.5 | AllplanAttributes - ash_lichte Raumhöhe: (7150-36+764+100)/1000-3.75; OKFF: 0; RoomName: Geräte
Rasterdecke | WUN-H2-E01-040 | CEILING | E3 0.1 m | 1166Dfl0000033528/03 | m² | Trockenbauarbeiten | 3 | 0.1 | 0 | 1 | Bekleidung | E3 | 0 | 0 | NEW | 2.5 | AllplanAttributes - Bezeichnung: Rasterdecke; ash_lichte Raumhöhe: (7150-36+764+100)/1000-3.75; OKFF: 0; RoomName: Geräte; Pset_CoveringCommon - AcousticRating: -
 | WUN-H2-E01-040 | CLADDING | 50 0.001 m | 1166Sfl0000665723/01 | m² | Maler- und Lackierarbeiten | 1 | 0.001 | 0 | 1 | Seitenfläche | 50 | 150 | 2500 | NEW
PVC Bahnenware Uni | WUN-H2-E01-032 | FLOORING | Ku2 0.15 m | 1166Bfl0000033443/01 | m² | Bodenbelagsarbeiten | 1 | 0.15 | 0 | 1 | Bodenfläche | Ku2 | 0 | 0 | NEW | AllplanAttributes - Bezeichnung: PVC Bahnenware Uni; Raumnr. Bauherr: 2.11_A2_02; ash B_Aufbau: B9; ash B_Rutschhemmung: R9
Gipsfaserplatten 2-lagig (BSK) | WUN-H2-E01-032 | CEILING | layer 0.036 m | 1166Dfl0000033442/01 | m² | Trockenbauarbeiten | 1 | 0.036 | 0 | 1 | Deckenfläche |  | 0 | 0 | NEW | 2.5 | AllplanAttributes - Bezeichnung: Gipsfaserplatten 2-lagig (BSK); RoomName: Wäsche rein
Gipsfaserplatten 2-lagig (BSK) | WUN-H2-E01-032 | CEILING | Installationshöhe 0.764 m | 1166Dfl0000033442/02 | m² | Trockenbauarbeiten | 2 | 0.764 | 0 | 1 | Bekleidung | Installationshöhe | 0 | 0 | NEW | 2.5 | AllplanAttributes - ash_lichte Raumhöhe: (7150-36+764+100)/1000-3.75; OKFF: 0; RoomName: Wäsche rein
Rasterdecke | WUN-H2-E01-032 | CEILING | E3 0.1 m | 1166Dfl0000033442/03 | m² | Trockenbauarbeiten | 3 | 0.1 | 0 | 1 | Bekleidung | E3 | 0 | 0 | NEW | 2.5 | AllplanAttributes - Bezeichnung: Rasterdecke; ash_lichte Raumhöhe: (7150-36+764+100)/1000-3.75; OKFF: 0; RoomName: Wäsche rein; Pset_CoveringCommon - AcousticRating: -
 | WUN-H2-E01-032 | CLADDING | 50 0.001 m | 1166Sfl0000665724/01 | m² | Maler- und Lackierarbeiten | 1 | 0.001 | 0 | 1 | Seitenfläche | 50 | 150 | 2500 | NEW
PVC | WUN-H2-E01-029 | FLOORING | Ku3 0.15 m | 1166Bfl0000033409/01 | m² | Bodenbelagsarbeiten | 1 | 0.15 | 0 | 1 | Bodenfläche | Ku3 | 0 | 0 | NEW | AllplanAttributes - Bezeichnung: PVC; Raumnr. Bauherr: 2.11_A2_02; ash B_Aufbau: B9; ash B_Rutschhemmung: R9
Gipsfaserplatten 2-lagig (BSK) | WUN-H2-E01-029 | CEILING | layer 0.036 m | 1166Dfl0000033410/01 | m² | Trockenbauarbeiten | 1 | 0.036 | 0 | 1 | Deckenfläche |  | 0 | 0 | NEW | 2.5 | AllplanAttributes - Bezeichnung: Gipsfaserplatten 2-lagig (BSK); RoomName: EDV
Gipsfaserplatten 2-lagig (BSK) | WUN-H2-E01-029 | CEILING | Installationshöhe 0.764 m | 1166Dfl0000033410/02 | m² | Trockenbauarbeiten | 2 | 0.764 | 0 | 1 | Bekleidung | Installationshöhe | 0 | 0 | NEW | 2.5 | AllplanAttributes - ash_lichte Raumhöhe: (7150-36+764+100)/1000-3.75; RoomName: EDV; Pset_CoveringCommon - AcousticRating: -
Rasterdecke | WUN-H2-E01-029 | CEILING | E3 0.1 m | 1166Dfl0000033410/03 | m² | Trockenbauarbeiten | 3 | 0.1 | 0 | 1 | Bekleidung | E3 | 0 | 0 | NEW | 2.5 | AllplanAttributes - Bezeichnung: Rasterdecke; ash_lichte Raumhöhe: (7150-36+764+100)/1000-3.75; OKFF: 0; RoomName: WC Pers.; Pset_CoveringCommon - AcousticRating: -
 | WUN-H2-E01-029 | CLADDING | 50 0.001 m | 1166Sfl0000665727/01 | m² | Maler- und Lackierarbeiten | 1 | 0.001 | 0 | 1 | Seitenfläche | 50 | 150 | 2500 | NEW
PVC Bahnenware Uni | WUN-H2-E01-026 | FLOORING | Ku2 0.15 m | 1166Bfl0000033376/01 | m² | Bodenbelagsarbeiten | 1 | 0.15 | 0 | 1 | Bodenfläche | Ku2 | 0 | 0 | NEW | AllplanAttributes - Bezeichnung: PVC Bahnenware Uni; Raumnr. Bauherr: 2.11_A2_02; ash B_Aufbau: B9; ash B_Rutschhemmung: R9
Gipsfaserplatten 2-lagig (BSK) | WUN-H2-E01-026 | CEILING | layer 0.036 m | 1166Dfl0000033377/01 | m² | Trockenbauarbeiten | 1 | 0.036 | 0 | 1 | Deckenfläche |  | 0 | 0 | NEW | 2.5 | AllplanAttributes - Bezeichnung: Gipsfaserplatten 2-lagig (BSK); RoomName: Lager Fixierbett
Gipsfaserplatten 2-lagig (BSK) | WUN-H2-E01-026 | CEILING | Installationshöhe 0.764 m | 1166Dfl0000033377/02 | m² | Trockenbauarbeiten | 2 | 0.764 | 0 | 1 | Bekleidung | Installationshöhe | 0 | 0 | NEW | 2.5 | AllplanAttributes - ash_lichte Raumhöhe: (7150-36+764+100)/1000-3.75; OKFF: 0; RoomName: Lager Fixierbett
Rasterdecke | WUN-H2-E01-026 | CEILING | E3 0.1 m | 1166Dfl0000033377/03 | m² | Trockenbauarbeiten | 3 | 0.1 | 0 | 1 | Bekleidung | E3 | 0 | 0 | NEW | 2.5 | AllplanAttributes - Bezeichnung: Rasterdecke; ash_lichte Raumhöhe: (7150-36+764+100)/1000-3.75; OKFF: 0; RoomName: Lager Fixierbett; Pset_CoveringCommon - AcousticRating: -
 | WUN-H2-E01-026 | CLADDING | 50 0.001 m | 1166Sfl0000665728/01 | m² | Maler- und Lackierarbeiten | 1 | 0.001 | 0 | 1 | Seitenfläche | 50 | 150 | 2500 | NEW
PVC Bahnenware Uni | WUN-H2-E01-038 | FLOORING | Ku2 0.15 m | 1166Bfl0000033453/01 | m² | Bodenbelagsarbeiten | 1 | 0.15 | 0 | 1 | Bodenfläche | Ku2 | 0 | 0 | NEW | AllplanAttributes - Bezeichnung: PVC Bahnenware Uni; Raumnr. Bauherr: 2.11_A2_02; ash B_Aufbau: B9; ash B_Rutschhemmung: R9
Gipsfaserplatten 2-lagig (BSK) | WUN-H2-E01-038 | CEILING | layer 0.036 m | 1166Dfl0000033454/01 | m² | Trockenbauarbeiten | 1 | 0.036 | 0 | 1 | Deckenfläche |  | 0 | 0 | NEW | 2.5 | AllplanAttributes - Bezeichnung: Gipsfaserplatten 2-lagig (BSK); RoomName: AR unrein
Gipsfaserplatten 2-lagig (BSK) | WUN-H2-E01-038 | CEILING | Installationshöhe 0.764 m | 1166Dfl0000033454/02 | m² | Trockenbauarbeiten | 2 | 0.764 | 0 | 1 | Bekleidung | Installationshöhe | 0 | 0 | NEW | 2.5 | AllplanAttributes - ash_lichte Raumhöhe: (7150-36+764+100)/1000-3.75; OKFF: 0; RoomName: AR unrein
Rasterdecke | WUN-H2-E01-038 | CEILING | E3 0.1 m | 1166Dfl0000033454/03 | m² | Trockenbauarbeiten | 3 | 0.1 | 0 | 1 | Bekleidung | E3 | 0 | 0 | NEW | 2.5 | AllplanAttributes - Bezeichnung: Rasterdecke; ash_lichte Raumhöhe: (7150-36+764+100)/1000-3.75; OKFF: 0; RoomName: AR unrein; Pset_CoveringCommon - AcousticRating: -
 | WUN-H2-E01-038 | CLADDING | 50 0.001 m | 1166Sfl0000665729/01 | m² | Maler- und Lackierarbeiten | 1 | 0.001 | 0 | 1 | Seitenfläche | 50 | 150 | 2500 | NEW
Fliesen Mosaik | WUN-H2-E01-039 | FLOORING | Fl2 0.15 m | 1166Bfl0000493617/01 | m² | Bodenbelagsarbeiten | 1 | 0.15 | 0 | 1 | Bodenfläche | Fl2 | 0 | 0 | NEW | AllplanAttributes - Bezeichnung: Fliesen Mosaik; Raumnr. Bauherr: 2.11_A2_02; ash B_Aufbau: B11; ash B_Rutschhemmung: R10; ash B_Bewertungsgruppe Barfußbereich: B
a-sh Wandbelag | WUN-H2-E01-039 | CLADDING | 68 0.01 m | 1166Sfl0000665500/01 | m² | Maler- und Lackierarbeiten | 1 | 0.01 | 0 | 1 | Seitenfläche | 68 | 100 | 3000 | NEW | AllplanAttributes - Bezeichnung: a-sh Wandbelag; Attributset-Objekt: Covering
Fliesen | WUN-H2-E01-039 | FLOORING | Fl1 0.15 m | 1166Bfl0000033517/01 | m² | Bodenbelagsarbeiten | 1 | 0.15 | 0 | 1 | Bodenfläche | Fl1 | 0 | 0 | NEW | AllplanAttributes - Bezeichnung: Fliesen; Raumnr. Bauherr: 2.11_A2_02; ash B_Aufbau: B10; ash B_Rutschhemmung: R10
Gipsfaserplatten 2-lagig (BSK) | WUN-H2-E01-039 | CEILING | layer 0.036 m | 1166Dfl0000033516/01 | m² | Trockenbauarbeiten | 1 | 0.036 | 0 | 1 | Deckenfläche |  | 0 | 0 | NEW | 2.5 | AllplanAttributes - Bezeichnung: Gipsfaserplatten 2-lagig (BSK); RoomName: Stationsbad
Gipsfaserplatten 2-lagig (BSK) | WUN-H2-E01-039 | CEILING | Installationshöhe 0.764 m | 1166Dfl0000033516/02 | m² | Trockenbauarbeiten | 2 | 0.764 | 0 | 1 | Bekleidung | Installationshöhe | 0 | 0 | NEW | 2.5 | AllplanAttributes - ash_lichte Raumhöhe: 2.500000; OKFF: 0; RoomName: Stationsbad
Gipskarton, imprägniert | WUN-H2-E01-039 | CEILING | B 0.1 m | 1166Dfl0000033516/03 | m² | Trockenbauarbeiten | 3 | 0.1 | 0 | 1 | Bekleidung | B | 0 | 0 | NEW | 2.5 | AllplanAttributes - Bezeichnung: Gipskarton, imprägniert; ash_lichte Raumhöhe: 2.500000; OKFF: 0; RoomName: Stationsbad; Pset_CoveringCommon - AcousticRating: -
Gipsfaserplatten 2-lagig (BSK) | WUN-H2-E01-039 | CEILING | D1 0.001 m | 1166Dfl0000033516/04 | m² | Maler- und Lackierarbeiten | 4 | 0.001 | 0 | 1 | Bekleidung | D1 | 0 | 0 | NEW | 2.5 | AllplanAttributes - ash_lichte Raumhöhe: 2.500000; OKFF: 0; RoomName: Stationsbad
 | WUN-H2-E01-039 | CLADDING | 50 0.001 m | 1166Sfl0000665730/01 | m² | Maler- und Lackierarbeiten | 1 | 0.001 | 0 | 1 | Seitenfläche | 50 | 150 | 2500 | NEW
Fliesen | WUN-H2-E01-030 | FLOORING | Fl1 0.15 m | 1166Bfl0000033420/01 | m² | Bodenbelagsarbeiten | 1 | 0.15 | 0 | 1 | Bodenfläche | Fl1 | 0 | 0 | NEW | AllplanAttributes - Bezeichnung: Fliesen; Raumnr. Bauherr: 2.11_A2_02; ash B_Aufbau: B10; ash B_Rutschhemmung: R10
Gipsfaserplatten 2-lagig (BSK) | WUN-H2-E01-030 | CEILING | layer 0.036 m | 1166Dfl0000033421/01 | m² | Trockenbauarbeiten | 1 | 0.036 | 0 | 1 | Deckenfläche |  | 0 | 0 | NEW | 2.5 | AllplanAttributes - Bezeichnung: Gipsfaserplatten 2-lagig (BSK); RoomName: WC Pers.
Gipsfaserplatten 2-lagig (BSK) | WUN-H2-E01-030 | CEILING | Installationshöhe 0.764 m | 1166Dfl0000033421/02 | m² | Trockenbauarbeiten | 2 | 0.764 | 0 | 1 | Bekleidung | Installationshöhe | 0 | 0 | NEW | 2.5 | AllplanAttributes - ash_lichte Raumhöhe: (7150-36+764+100)/1000-3.75; OKFF: 0; RoomName: WC Pers.
Rasterdecke | WUN-H2-E01-030 | CEILING | E3 0.1 m | 1166Dfl0000033421/03 | m² | Trockenbauarbeiten | 3 | 0.1 | 0 | 1 | Bekleidung | E3 | 0 | 0 | NEW | 2.5 | AllplanAttributes - Bezeichnung: Rasterdecke; ash_lichte Raumhöhe: (7150-36+764+100)/1000-3.75; OKFF: 0; RoomName: WC Pers.; Pset_CoveringCommon - AcousticRating: -
 | WUN-H2-E01-030 | CLADDING | 50 0.001 m | 1166Sfl0000665800/01 | m² | Maler- und Lackierarbeiten | 1 | 0.001 | 0 | 1 | Seitenfläche | 50 | 150 | 2500 | NEW
a-sh Wandbelag | WUN-H2-E01-030 | CLADDING | 65 0.01 m | 1166Sfl0000665647/01 | m² | Maler- und Lackierarbeiten | 1 | 0.01 | 0 | 1 | Seitenfläche | 65 | 100 | 3000 | NEW | AllplanAttributes - Bezeichnung: a-sh Wandbelag; Attributset-Objekt: Covering
Fliesen | WUN-H2-E01-031 | FLOORING | Fl1 0.15 m | 1166Bfl0000033431/01 | m² | Bodenbelagsarbeiten | 1 | 0.15 | 0 | 1 | Bodenfläche | Fl1 | 0 | 0 | NEW | AllplanAttributes - Bezeichnung: Fliesen; Raumnr. Bauherr: 2.11_A2_02; ash B_Aufbau: B10; ash B_Rutschhemmung: R10
Gipsfaserplatten 2-lagig (BSK) | WUN-H2-E01-031 | CEILING | layer 0.036 m | 1166Dfl0000033432/01 | m² | Trockenbauarbeiten | 1 | 0.036 | 0 | 1 | Deckenfläche |  | 0 | 0 | NEW | 2.5 | AllplanAttributes - Bezeichnung: Gipsfaserplatten 2-lagig (BSK); RoomName: WC Pers.
Gipsfaserplatten 2-lagig (BSK) | WUN-H2-E01-031 | CEILING | Installationshöhe 0.764 m | 1166Dfl0000033432/02 | m² | Trockenbauarbeiten | 2 | 0.764 | 0 | 1 | Bekleidung | Installationshöhe | 0 | 0 | NEW | 2.5 | AllplanAttributes - ash_lichte Raumhöhe: (7150-36+764+100)/1000-3.75; OKFF: 0; RoomName: WC Pers.
Rasterdecke | WUN-H2-E01-031 | CEILING | E3 0.1 m | 1166Dfl0000033432/03 | m² | Trockenbauarbeiten | 3 | 0.1 | 0 | 1 | Bekleidung | E3 | 0 | 0 | NEW | 2.5 | AllplanAttributes - Bezeichnung: Rasterdecke; ash_lichte Raumhöhe: (7150-36+764+100)/1000-3.75; OKFF: 0; RoomName: WC Pers.; Pset_CoveringCommon - AcousticRating: -
 | WUN-H2-E01-031 | CLADDING | 50 0.001 m | 1166Sfl0000665731/01 | m² | Maler- und Lackierarbeiten | 1 | 0.001 | 0 | 1 | Seitenfläche | 50 | 150 | 2500 | NEW
a-sh Wandbelag | WUN-H2-E01-031 | CLADDING | 65 0.01 m | 1166Sfl0000665578/01 | m² | Maler- und Lackierarbeiten | 1 | 0.01 | 0 | 1 | Seitenfläche | 65 | 100 | 3000 | NEW | AllplanAttributes - Bezeichnung: a-sh Wandbelag; Attributset-Objekt: Covering
Gipsfaserplatten 2-lagig (BSK) | WUN-H2-E01-007 | CEILING | layer 0.036 m | 1166Dfl0000033172/01 | m² | Trockenbauarbeiten | 1 | 0.036 | 0 | 1 | Deckenfläche |  | 0 | 0 | NEW | 2.5 | AllplanAttributes - Bezeichnung: Gipsfaserplatten 2-lagig (BSK); RoomName: Gespräch
Gipsfaserplatten 2-lagig (BSK) | WUN-H2-E01-007 | CEILING | Installationshöhe 0.714 m | 1166Dfl0000033172/02 | m² | Trockenbauarbeiten | 2 | 0.714 | 0 | 1 | Bekleidung | Installationshöhe | 0 | 0 | NEW | 2.5 | AllplanAttributes - ash_lichte Raumhöhe: 2.500000; OKFF: 0; RoomName: Gespräch
Gipsfaserplatten 2-lagig (BSK) | WUN-H2-E01-007 | CEILING | A1 0.15 m | 1166Dfl0000033172/03 | m² | Trockenbauarbeiten | 3 | 0.15 | 0 | 1 | Bekleidung | A1 | 0 | 0 | NEW | 2.5 | AllplanAttributes - ash_lichte Raumhöhe: 2.500000; OKFF: 0; RoomName: Gespräch; Pset_CoveringCommon - AcousticRating: -
Gipsfaserplatten 2-lagig (BSK) | WUN-H2-E01-007 | CEILING | D1 0.001 m | 1166Dfl0000033172/04 | m² | Maler- und Lackierarbeiten | 4 | 0.001 | 0 | 1 | Bekleidung | D1 | 0 | 0 | NEW | 2.5 | AllplanAttributes - ash_lichte Raumhöhe: 2.500000; OKFF: 0; RoomName: Gespräch
Gipsfaserplatten 2-lagig (BSK) | WUN-H2-E01-007 | CEILING | layer 0.036 m | 1166Dfl0000223354/01 | m² | Trockenbauarbeiten | 1 | 0.036 | 0 | 1 | Deckenfläche |  | 0 | 0 | NEW | 2.5 | AllplanAttributes - Bezeichnung: Gipsfaserplatten 2-lagig (BSK); RoomName: Gespräch
Gipsfaserplatten 2-lagig (BSK) | WUN-H2-E01-007 | CEILING | Installationshöhe 0.714 m | 1166Dfl0000223354/02 | m² | Trockenbauarbeiten | 2 | 0.714 | 0 | 1 | Bekleidung | Installationshöhe | 0 | 0 | NEW | 2.5 | AllplanAttributes - ash_lichte Raumhöhe: 2.500000; OKFF: 0; RoomName: Gespräch
Gipsfaserplatten 2-lagig (BSK) | WUN-H2-E01-007 | CEILING | Aa 0.15 m | 1166Dfl0000223354/03 | m² | Trockenbauarbeiten | 3 | 0.15 | 0 | 1 | Bekleidung | Aa | 0 | 0 | NEW | 2.5 | AllplanAttributes - ash_lichte Raumhöhe: 2.500000; OKFF: 0; RoomName: Gespräch; Pset_CoveringCommon - AcousticRating: -
Gipsfaserplatten 2-lagig (BSK) | WUN-H2-E01-007 | CEILING | D1 0.001 m | 1166Dfl0000223354/04 | m² | Maler- und Lackierarbeiten | 4 | 0.001 | 0 | 1 | Bekleidung | D1 | 0 | 0 | NEW | 2.5 | AllplanAttributes - ash_lichte Raumhöhe: 2.500000; OKFF: 0; RoomName: Gespräch
PVC Bahnenware Holzoptik | WUN-H2-E01-007 | FLOORING | Ku1 0.15 m | 1166Bfl0000033161/01 | m² | Bodenbelagsarbeiten | 1 | 0.15 | 0 | 1 | Bodenfläche | Ku1 | 0 | 0 | NEW | AllplanAttributes - Bezeichnung: PVC Bahnenware Holzoptik; Raumnr. Bauherr: 2.11_A2_02; ash B_Aufbau: B9; ash B_Rutschhemmung: R9
 | WUN-H2-E01-007 | CLADDING | 49 0.001 m | 1166Sfl0000666352/01 | m² | Maler- und Lackierarbeiten | 1 | 0.001 | 0 | 1 | Seitenfläche | 49 | 150 | 3150 | NEW
Gipsfaserplatten 2-lagig (BSK) | WUN-H2-E01-009 | CEILING | layer 0.036 m | 1166Dfl0000441703/01 | m² | Trockenbauarbeiten | 1 | 0.036 | 0 | 1 | Deckenfläche |  | 0 | 0 | NEW | 2.5 | AllplanAttributes - Bezeichnung: Gipsfaserplatten 2-lagig (BSK); RoomName: Ruheraum
Gipsfaserplatten 2-lagig (BSK) | WUN-H2-E01-009 | CEILING | Installationshöhe 0.764 m | 1166Dfl0000441703/02 | m² | Trockenbauarbeiten | 2 | 0.764 | 0 | 1 | Bekleidung | Installationshöhe | 0 | 0 | NEW | 2.5 | AllplanAttributes - ash_lichte Raumhöhe: 2.500000; OKFF: 0; RoomName: Ruheraum
Kühldecke glatt | WUN-H2-E01-009 | CEILING | H7a 0.1 m | 1166Dfl0000441703/03 | m² | Trockenbauarbeiten | 3 | 0.1 | 0 | 1 | Bekleidung | H7a | 0 | 0 | NEW | 2.5 | AllplanAttributes - Bezeichnung: Kühldecke glatt; ash_lichte Raumhöhe: 2.500000; OKFF: 0; RoomName: Ruheraum; Pset_CoveringCommon - AcousticRating: -
Gipsfaserplatten 2-lagig (BSK) | WUN-H2-E01-009 | CEILING | D1 0.001 m | 1166Dfl0000441703/04 | m² | Maler- und Lackierarbeiten | 4 | 0.001 | 0 | 1 | Bekleidung | D1 | 0 | 0 | NEW | 2.5 | AllplanAttributes - ash_lichte Raumhöhe: 2.500000; OKFF: 0; RoomName: Ruheraum
PVC Bahnenware Holzoptik | WUN-H2-E01-009 | FLOORING | Ku1 0.15 m | 1166Bfl0000033188/01 | m² | Bodenbelagsarbeiten | 1 | 0.15 | 0 | 1 | Bodenfläche | Ku1 | 0 | 0 | NEW | AllplanAttributes - Bezeichnung: PVC Bahnenware Holzoptik; Raumnr. Bauherr: 2.11_A2_02; ash B_Aufbau: B9; ash B_Rutschhemmung: R9
Gipsfaserplatten 2-lagig (BSK) | WUN-H2-E01-009 | CEILING | layer 0.036 m | 1166Dfl0000033187/01 | m² | Trockenbauarbeiten | 1 | 0.036 | 0 | 1 | Deckenfläche |  | 0 | 0 | NEW | 2.5 | AllplanAttributes - Bezeichnung: Gipsfaserplatten 2-lagig (BSK); RoomName: U/B-Raum
Gipsfaserplatten 2-lagig (BSK) | WUN-H2-E01-009 | CEILING | Installationshöhe 0.764 m | 1166Dfl0000033187/02 | m² | Trockenbauarbeiten | 2 | 0.764 | 0 | 1 | Bekleidung | Installationshöhe | 0 | 0 | NEW | 2.5 | AllplanAttributes - ash_lichte Raumhöhe: 2.500000; OKFF: 0; RoomName: U/B-Raum
Kühldecke glatt | WUN-H2-E01-009 | CEILING | H7a 0.1 m | 1166Dfl0000033187/03 | m² | Trockenbauarbeiten | 3 | 0.1 | 0 | 1 | Bekleidung | H7a | 0 | 0 | NEW | 2.5 | AllplanAttributes - Bezeichnung: Kühldecke glatt; ash_lichte Raumhöhe: 2.500000; OKFF: 0; RoomName: U/B-Raum; Pset_CoveringCommon - AcousticRating: -
Gipsfaserplatten 2-lagig (BSK) | WUN-H2-E01-009 | CEILING | D1 0.001 m | 1166Dfl0000033187/04 | m² | Maler- und Lackierarbeiten | 4 | 0.001 | 0 | 1 | Bekleidung | D1 | 0 | 0 | NEW | 2.5 | AllplanAttributes - ash_lichte Raumhöhe: 2.500000; OKFF: 0; RoomName: U/B-Raum
 | WUN-H2-E01-009 | CLADDING | 49 0.001 m | 1166Sfl0000666644/01 | m² | Maler- und Lackierarbeiten | 1 | 0.001 | 0 | 1 | Seitenfläche | 49 | 150 | 3150 | NEW
Gipsfaserplatten 2-lagig (BSK) | WUN-H2-E01-067 | CEILING | layer 0.036 m | 1166Dfl0000447400/01 | m² | Trockenbauarbeiten | 1 | 0.036 | 0 | 1 | Deckenfläche |  | 0 | 0 | NEW | 2.5 | AllplanAttributes - Bezeichnung: Gipsfaserplatten 2-lagig (BSK); RoomName: Ruheraum
Gipsfaserplatten 2-lagig (BSK) | WUN-H2-E01-067 | CEILING | Installationshöhe 0.764 m | 1166Dfl0000447400/02 | m² | Trockenbauarbeiten | 2 | 0.764 | 0 | 1 | Bekleidung | Installationshöhe | 0 | 0 | NEW | 2.5 | AllplanAttributes - ash_lichte Raumhöhe: 2.500000; OKFF: 0; RoomName: Ruheraum
Kühldecke glatt | WUN-H2-E01-067 | CEILING | H7a 0.1 m | 1166Dfl0000447400/03 | m² | Trockenbauarbeiten | 3 | 0.1 | 0 | 1 | Bekleidung | H7a | 0 | 0 | NEW | 2.5 | AllplanAttributes - Bezeichnung: Kühldecke glatt; ash_lichte Raumhöhe: 2.500000; OKFF: 0; RoomName: Ruheraum; Pset_CoveringCommon - AcousticRating: -
Gipsfaserplatten 2-lagig (BSK) | WUN-H2-E01-067 | CEILING | D1 0.001 m | 1166Dfl0000447400/04 | m² | Maler- und Lackierarbeiten | 4 | 0.001 | 0 | 1 | Bekleidung | D1 | 0 | 0 | NEW | 2.5 | AllplanAttributes - ash_lichte Raumhöhe: 2.500000; OKFF: 0; RoomName: Ruheraum
PVC Bahnenware Holzoptik | WUN-H2-E01-067 | FLOORING | Ku1 0.15 m | 1166Bfl0000034253/01 | m² | Bodenbelagsarbeiten | 1 | 0.15 | 0 | 1 | Bodenfläche | Ku1 | 0 | 0 | NEW | AllplanAttributes - Bezeichnung: PVC Bahnenware Holzoptik; Raumnr. Bauherr: 2.11_A2_02; ash B_Aufbau: B9; ash B_Rutschhemmung: R9
Gipsfaserplatten 2-lagig (BSK) | WUN-H2-E01-067 | CEILING | layer 0.036 m | 1166Dfl0000034252/01 | m² | Trockenbauarbeiten | 1 | 0.036 | 0 | 1 | Deckenfläche |  | 0 | 0 | NEW | 2.5 | AllplanAttributes - Bezeichnung: Gipsfaserplatten 2-lagig (BSK); RoomName: U/B-Raum
Gipsfaserplatten 2-lagig (BSK) | WUN-H2-E01-067 | CEILING | Installationshöhe 0.764 m | 1166Dfl0000034252/02 | m² | Trockenbauarbeiten | 2 | 0.764 | 0 | 1 | Bekleidung | Installationshöhe | 0 | 0 | NEW | 2.5 | AllplanAttributes - ash_lichte Raumhöhe: 2.500000; OKFF: 0; RoomName: U/B-Raum
Kühldecke glatt | WUN-H2-E01-067 | CEILING | H7a 0.1 m | 1166Dfl0000034252/03 | m² | Trockenbauarbeiten | 3 | 0.1 | 0 | 1 | Bekleidung | H7a | 0 | 0 | NEW | 2.5 | AllplanAttributes - Bezeichnung: Kühldecke glatt; ash_lichte Raumhöhe: 2.500000; OKFF: 0; RoomName: U/B-Raum; Pset_CoveringCommon - AcousticRating: -
Gipsfaserplatten 2-lagig (BSK) | WUN-H2-E01-067 | CEILING | D1 0.001 m | 1166Dfl0000034252/04 | m² | Maler- und Lackierarbeiten | 4 | 0.001 | 0 | 1 | Bekleidung | D1 | 0 | 0 | NEW | 2.5 | AllplanAttributes - ash_lichte Raumhöhe: 2.500000; OKFF: 0; RoomName: U/B-Raum
 | WUN-H2-E01-067 | CLADDING | 49 0.001 m | 1166Sfl0000666645/01 | m² | Maler- und Lackierarbeiten | 1 | 0.001 | 0 | 1 | Seitenfläche | 49 | 150 | 3150 | NEW
PVC Bahnenware Holzoptik | WUN-H2-E01-012 | FLOORING | Ku1 0.15 m | 1166Bfl0000034682/01 | m² | Bodenbelagsarbeiten | 1 | 0.15 | 0 | 1 | Bodenfläche | Ku1 | 0 | 0 | NEW | AllplanAttributes - Bezeichnung: PVC Bahnenware Holzoptik; Raumnr. Bauherr: 2.11_A2_02; ash B_Aufbau: B9; ash B_Rutschhemmung: R9
Gipsfaserplatten 2-lagig (BSK) | WUN-H2-E01-012 | CEILING | layer 0.036 m | 1166Dfl0000034681/01 | m² | Trockenbauarbeiten | 1 | 0.036 | 0 | 1 | Deckenfläche |  | 0 | 0 | NEW | 2.5 | AllplanAttributes - Bezeichnung: Gipsfaserplatten 2-lagig (BSK); RoomName: Vorraum Krisenzimmer
Gipsfaserplatten 2-lagig (BSK) | WUN-H2-E01-012 | CEILING | Installationshöhe 0.764 m | 1166Dfl0000034681/02 | m² | Trockenbauarbeiten | 2 | 0.764 | 0 | 1 | Bekleidung | Installationshöhe | 0 | 0 | NEW | 2.5 | AllplanAttributes - ash_lichte Raumhöhe: 2.500000; OKFF: 0; RoomName: Vorraum Krisenzimmer
Gipsfaserplatten 2-lagig (BSK) | WUN-H2-E01-012 | CEILING | A1 0.1 m | 1166Dfl0000034681/03 | m² | Trockenbauarbeiten | 3 | 0.1 | 0 | 1 | Bekleidung | A1 | 0 | 0 | NEW | 2.5 | AllplanAttributes - ash_lichte Raumhöhe: 2.500000; OKFF: 0; RoomName: Vorraum Krisenzimmer; Pset_CoveringCommon - AcousticRating: -
Gipsfaserplatten 2-lagig (BSK) | WUN-H2-E01-012 | CEILING | D1 0.001 m | 1166Dfl0000034681/04 | m² | Maler- und Lackierarbeiten | 4 | 0.001 | 0 | 1 | Bekleidung | D1 | 0 | 0 | NEW | 2.5 | AllplanAttributes - ash_lichte Raumhöhe: 2.500000; OKFF: 0; RoomName: Vorraum Krisenzimmer
 | WUN-H2-E01-012 | CLADDING | 49 0.001 m | 1166Sfl0000666646/01 | m² | Maler- und Lackierarbeiten | 1 | 0.001 | 0 | 1 | Seitenfläche | 49 | 150 | 3150 | NEW
PVC Bahnenware Holzoptik | WUN-H2-E01-064 | FLOORING | Ku1 0.15 m | 1166Bfl0000034693/01 | m² | Bodenbelagsarbeiten | 1 | 0.15 | 0 | 1 | Bodenfläche | Ku1 | 0 | 0 | NEW | AllplanAttributes - Bezeichnung: PVC Bahnenware Holzoptik; Raumnr. Bauherr: 2.11_A2_02; ash B_Aufbau: B9; ash B_Rutschhemmung: R9
Gipsfaserplatten 2-lagig (BSK) | WUN-H2-E01-064 | CEILING | layer 0.036 m | 1166Dfl0000034692/01 | m² | Trockenbauarbeiten | 1 | 0.036 | 0 | 1 | Deckenfläche |  | 0 | 0 | NEW | 2.5 | AllplanAttributes - Bezeichnung: Gipsfaserplatten 2-lagig (BSK); RoomName: Vorraum Krisenzimmer
Gipsfaserplatten 2-lagig (BSK) | WUN-H2-E01-064 | CEILING | Installationshöhe 0.764 m | 1166Dfl0000034692/02 | m² | Trockenbauarbeiten | 2 | 0.764 | 0 | 1 | Bekleidung | Installationshöhe | 0 | 0 | NEW | 2.5 | AllplanAttributes - ash_lichte Raumhöhe: 2.500000; OKFF: 0; RoomName: Vorraum Krisenzimmer
Gipsfaserplatten 2-lagig (BSK) | WUN-H2-E01-064 | CEILING | A1 0.1 m | 1166Dfl0000034692/03 | m² | Trockenbauarbeiten | 3 | 0.1 | 0 | 1 | Bekleidung | A1 | 0 | 0 | NEW | 2.5 | AllplanAttributes - ash_lichte Raumhöhe: 2.500000; OKFF: 0; RoomName: Vorraum Krisenzimmer; Pset_CoveringCommon - AcousticRating: -
Gipsfaserplatten 2-lagig (BSK) | WUN-H2-E01-064 | CEILING | D1 0.001 m | 1166Dfl0000034692/04 | m² | Maler- und Lackierarbeiten | 4 | 0.001 | 0 | 1 | Bekleidung | D1 | 0 | 0 | NEW | 2.5 | AllplanAttributes - ash_lichte Raumhöhe: 2.500000; OKFF: 0; RoomName: Vorraum Krisenzimmer
 | WUN-H2-E01-064 | CLADDING | 49 0.001 m | 1166Sfl0000666647/01 | m² | Maler- und Lackierarbeiten | 1 | 0.001 | 0 | 1 | Seitenfläche | 49 | 150 | 3150 | NEW
Gipsfaserplatten 2-lagig (BSK) | WUN-H2-E01-058 | CEILING | layer 0.036 m | 1166Dfl0000034126/01 | m² | Trockenbauarbeiten | 1 | 0.036 | 0 | 1 | Deckenfläche |  | 0 | 0 | NEW | 2.5 | AllplanAttributes - Bezeichnung: Gipsfaserplatten 2-lagig (BSK); RoomName: Ergo- / Kunsttherapie
Gipsfaserplatten 2-lagig (BSK) | WUN-H2-E01-058 | CEILING | Installationshöhe 0.714 m | 1166Dfl0000034126/02 | m² | Trockenbauarbeiten | 2 | 0.714 | 0 | 1 | Bekleidung | Installationshöhe | 0 | 0 | NEW | 2.5 | AllplanAttributes - ash_lichte Raumhöhe: 2.500000; OKFF: 0; RoomName: Ergo- / Kunsttherapie
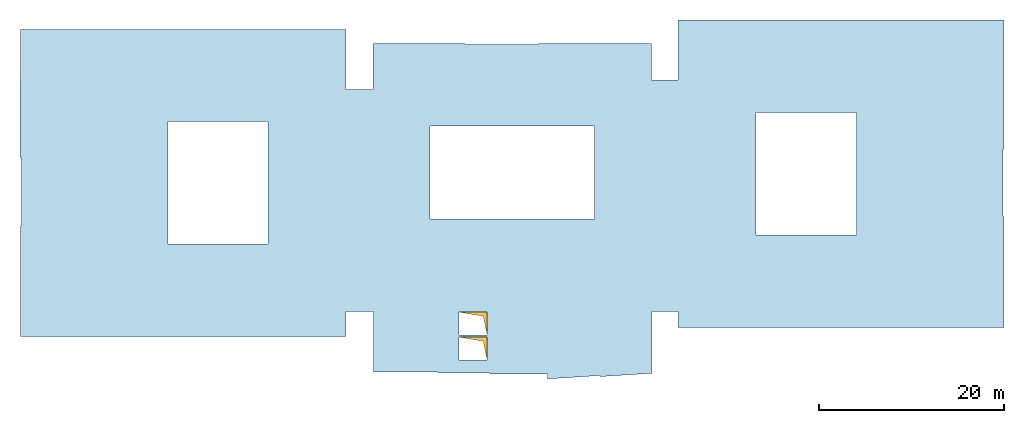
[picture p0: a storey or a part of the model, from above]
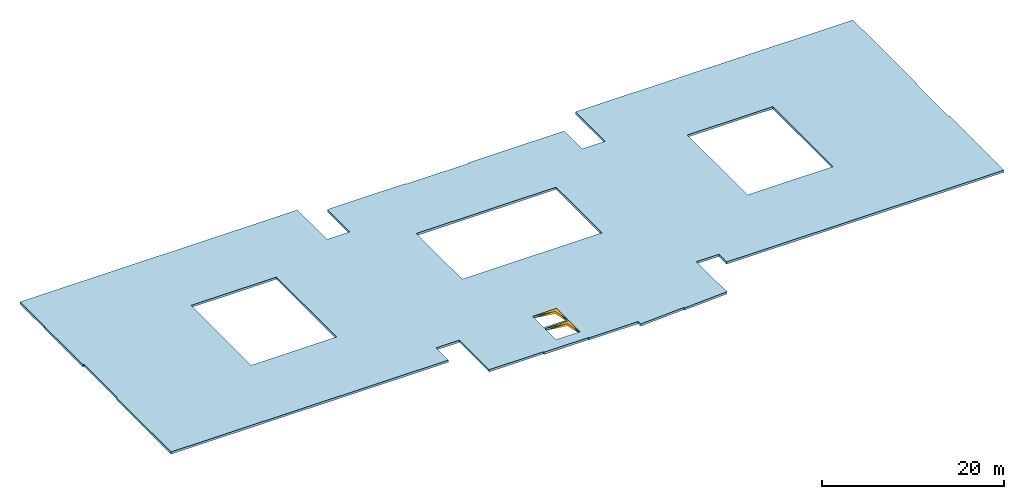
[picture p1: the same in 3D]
Properties of the parts of a building model (IFC4), part 15 of 80

# IfcCovering (3945)
Name | In | PredefinedType | Material | Allright_Bauteil_ID | Abrechnungsart | Gewerk | Schichtnummer | Schichtdicke (m) | Dicke (m) | Faktor | Objektname | AllplanAttributes, Material | Bezugshöhe | Deltahöhe | Status | D_lichte Raumhöhe [Zahl] (m)
Gipsfaserplatten 2-lagig (BSK) | WUN-H2-E01-058 | CEILING | A1 0.15 m | 1166Dfl0000034126/03 | m² | Trockenbauarbeiten | 3 | 0.15 | 0 | 1 | Bekleidung | A1 | 0 | 0 | NEW | 2.5 | AllplanAttributes - ash_lichte Raumhöhe: 2.500000; OKFF: 0; RoomName: Ergo- / Kunsttherapie; Pset_CoveringCommon - AcousticRating: -
Gipsfaserplatten 2-lagig (BSK) | WUN-H2-E01-058 | CEILING | D1 0.001 m | 1166Dfl0000034126/04 | m² | Maler- und Lackierarbeiten | 4 | 0.001 | 0 | 1 | Bekleidung | D1 | 0 | 0 | NEW | 2.5 | AllplanAttributes - ash_lichte Raumhöhe: 2.500000; OKFF: 0; RoomName: Ergo- / Kunsttherapie
Gipsfaserplatten 2-lagig (BSK) | WUN-H2-E01-058 | CEILING | layer 0.036 m | 1166Dfl0000234012/01 | m² | Trockenbauarbeiten | 1 | 0.036 | 0 | 1 | Deckenfläche |  | 0 | 0 | NEW | 2.5 | AllplanAttributes - Bezeichnung: Gipsfaserplatten 2-lagig (BSK); RoomName: Freizeit / Club
Gipsfaserplatten 2-lagig (BSK) | WUN-H2-E01-058 | CEILING | Installationshöhe 0.714 m | 1166Dfl0000234012/02 | m² | Trockenbauarbeiten | 2 | 0.714 | 0 | 1 | Bekleidung | Installationshöhe | 0 | 0 | NEW | 2.5 | AllplanAttributes - ash_lichte Raumhöhe: 2.500000; OKFF: 0; RoomName: Freizeit / Club
Gipsfaserplatten 2-lagig (BSK) | WUN-H2-E01-058 | CEILING | Aa 0.15 m | 1166Dfl0000234012/03 | m² | Trockenbauarbeiten | 3 | 0.15 | 0 | 1 | Bekleidung | Aa | 0 | 0 | NEW | 2.5 | AllplanAttributes - ash_lichte Raumhöhe: 2.500000; OKFF: 0; RoomName: Freizeit / Club; Pset_CoveringCommon - AcousticRating: -
Gipsfaserplatten 2-lagig (BSK) | WUN-H2-E01-058 | CEILING | D1 0.001 m | 1166Dfl0000234012/04 | m² | Maler- und Lackierarbeiten | 4 | 0.001 | 0 | 1 | Bekleidung | D1 | 0 | 0 | NEW | 2.5 | AllplanAttributes - ash_lichte Raumhöhe: 2.500000; OKFF: 0; RoomName: Freizeit / Club
PVC Bahnenware Holzoptik | WUN-H2-E01-058 | FLOORING | Ku1 0.15 m | 1166Bfl0000034115/01 | m² | Bodenbelagsarbeiten | 1 | 0.15 | 0 | 1 | Bodenfläche | Ku1 | 0 | 0 | NEW | AllplanAttributes - Bezeichnung: PVC Bahnenware Holzoptik; Raumnr. Bauherr: 2.11_A2_02; ash B_Aufbau: B9; ash B_Rutschhemmung: R9
 | WUN-H2-E01-058 | CLADDING | 49 0.001 m | 1166Sfl0000666648/01 | m² | Maler- und Lackierarbeiten | 1 | 0.001 | 0 | 1 | Seitenfläche | 49 | 150 | 3150 | NEW
Gipsfaserplatten 2-lagig (BSK) | WUN-H2-E01-010 | CEILING | layer 0.036 m | 1166Dfl0000033209/01 | m² | Trockenbauarbeiten | 1 | 0.036 | 0 | 1 | Deckenfläche |  | 0 | 0 | NEW | 2.5 | AllplanAttributes - Bezeichnung: Gipsfaserplatten 2-lagig (BSK); RoomName: Ruheraum
Gipsfaserplatten 2-lagig (BSK) | WUN-H2-E01-010 | CEILING | Installationshöhe 0.764 m | 1166Dfl0000033209/02 | m² | Trockenbauarbeiten | 2 | 0.764 | 0 | 1 | Bekleidung | Installationshöhe | 0 | 0 | NEW | 2.5 | AllplanAttributes - ash_lichte Raumhöhe: 2.500000; OKFF: 0; RoomName: Ruheraum
Kühldecke glatt | WUN-H2-E01-010 | CEILING | H7a 0.1 m | 1166Dfl0000033209/03 | m² | Trockenbauarbeiten | 3 | 0.1 | 0 | 1 | Bekleidung | H7a | 0 | 0 | NEW | 2.5 | AllplanAttributes - Bezeichnung: Kühldecke glatt; ash_lichte Raumhöhe: 2.500000; OKFF: 0; RoomName: Ruheraum; Pset_CoveringCommon - AcousticRating: -
Gipsfaserplatten 2-lagig (BSK) | WUN-H2-E01-010 | CEILING | D1 0.001 m | 1166Dfl0000033209/04 | m² | Maler- und Lackierarbeiten | 4 | 0.001 | 0 | 1 | Bekleidung | D1 | 0 | 0 | NEW | 2.5 | AllplanAttributes - ash_lichte Raumhöhe: 2.500000; OKFF: 0; RoomName: Ruheraum
Gipsfaserplatten 2-lagig (BSK) | WUN-H2-E01-010 | CEILING | layer 0.036 m | 1166Dfl0000442155/01 | m² | Trockenbauarbeiten | 1 | 0.036 | 0 | 1 | Deckenfläche |  | 0 | 0 | NEW | 2.5 | AllplanAttributes - Bezeichnung: Gipsfaserplatten 2-lagig (BSK); RoomName: Ruheraum
Gipsfaserplatten 2-lagig (BSK) | WUN-H2-E01-010 | CEILING | Installationshöhe 0.764 m | 1166Dfl0000442155/02 | m² | Trockenbauarbeiten | 2 | 0.764 | 0 | 1 | Bekleidung | Installationshöhe | 0 | 0 | NEW | 2.5 | AllplanAttributes - ash_lichte Raumhöhe: 2.500000; OKFF: 0; RoomName: Ruheraum
Kühldecke gelocht | WUN-H2-E01-010 | CEILING | H7b 0.1 m | 1166Dfl0000442155/03 | m² | Trockenbauarbeiten | 3 | 0.1 | 0 | 1 | Bekleidung | H7b | 0 | 0 | NEW | 2.5 | AllplanAttributes - Bezeichnung: Kühldecke gelocht; ash_lichte Raumhöhe: 2.500000; OKFF: 0; RoomName: Ruheraum; Pset_CoveringCommon - AcousticRating: -
Gipsfaserplatten 2-lagig (BSK) | WUN-H2-E01-010 | CEILING | D1 0.001 m | 1166Dfl0000442155/04 | m² | Maler- und Lackierarbeiten | 4 | 0.001 | 0 | 1 | Bekleidung | D1 | 0 | 0 | NEW | 2.5 | AllplanAttributes - ash_lichte Raumhöhe: 2.500000; OKFF: 0; RoomName: Ruheraum
PVC Bahnenware Holzoptik | WUN-H2-E01-010 | FLOORING | Ku1 0.15 m | 1166Bfl0000033199/01 | m² | Bodenbelagsarbeiten | 1 | 0.15 | 0 | 1 | Bodenfläche | Ku1 | 0 | 0 | NEW | AllplanAttributes - Bezeichnung: PVC Bahnenware Holzoptik; Raumnr. Bauherr: 2.11_A2_02; ash B_Aufbau: B9; ash B_Rutschhemmung: R9
 | WUN-H2-E01-010 | CLADDING | 49 0.001 m | 1166Sfl0000666649/01 | m² | Maler- und Lackierarbeiten | 1 | 0.001 | 0 | 1 | Seitenfläche | 49 | 150 | 3150 | NEW
Gipsfaserplatten 2-lagig (BSK) | WUN-H2-E01-059 | CEILING | layer 0.036 m | 1166Dfl0000034139/01 | m² | Trockenbauarbeiten | 1 | 0.036 | 0 | 1 | Deckenfläche |  | 0 | 0 | NEW | 2.5 | AllplanAttributes - Bezeichnung: Gipsfaserplatten 2-lagig (BSK); RoomName: Freizeit / Club
Gipsfaserplatten 2-lagig (BSK) | WUN-H2-E01-059 | CEILING | Installationshöhe 0.714 m | 1166Dfl0000034139/02 | m² | Trockenbauarbeiten | 2 | 0.714 | 0 | 1 | Bekleidung | Installationshöhe | 0 | 0 | NEW | 2.5 | AllplanAttributes - ash_lichte Raumhöhe: 2.500000; OKFF: 0; RoomName: Freizeit / Club
Gipsfaserplatten 2-lagig (BSK) | WUN-H2-E01-059 | CEILING | A1 0.15 m | 1166Dfl0000034139/03 | m² | Trockenbauarbeiten | 3 | 0.15 | 0 | 1 | Bekleidung | A1 | 0 | 0 | NEW | 2.5 | AllplanAttributes - ash_lichte Raumhöhe: 2.500000; OKFF: 0; RoomName: Freizeit / Club; Pset_CoveringCommon - AcousticRating: -
Gipsfaserplatten 2-lagig (BSK) | WUN-H2-E01-059 | CEILING | D1 0.001 m | 1166Dfl0000034139/04 | m² | Maler- und Lackierarbeiten | 4 | 0.001 | 0 | 1 | Bekleidung | D1 | 0 | 0 | NEW | 2.5 | AllplanAttributes - ash_lichte Raumhöhe: 2.500000; OKFF: 0; RoomName: Freizeit / Club
Gipsfaserplatten 2-lagig (BSK) | WUN-H2-E01-059 | CEILING | layer 0.036 m | 1166Dfl0000233432/01 | m² | Trockenbauarbeiten | 1 | 0.036 | 0 | 1 | Deckenfläche |  | 0 | 0 | NEW | 2.5 | AllplanAttributes - Bezeichnung: Gipsfaserplatten 2-lagig (BSK); RoomName: Freizeit / Club
Gipsfaserplatten 2-lagig (BSK) | WUN-H2-E01-059 | CEILING | Installationshöhe 0.714 m | 1166Dfl0000233432/02 | m² | Trockenbauarbeiten | 2 | 0.714 | 0 | 1 | Bekleidung | Installationshöhe | 0 | 0 | NEW | 2.5 | AllplanAttributes - ash_lichte Raumhöhe: 2.500000; OKFF: 0; RoomName: Freizeit / Club
Gipsfaserplatten 2-lagig (BSK) | WUN-H2-E01-059 | CEILING | Aa 0.15 m | 1166Dfl0000233432/03 | m² | Trockenbauarbeiten | 3 | 0.15 | 0 | 1 | Bekleidung | Aa | 0 | 0 | NEW | 2.5 | AllplanAttributes - ash_lichte Raumhöhe: 2.500000; OKFF: 0; RoomName: Freizeit / Club; Pset_CoveringCommon - AcousticRating: -
Gipsfaserplatten 2-lagig (BSK) | WUN-H2-E01-059 | CEILING | D1 0.001 m | 1166Dfl0000233432/04 | m² | Maler- und Lackierarbeiten | 4 | 0.001 | 0 | 1 | Bekleidung | D1 | 0 | 0 | NEW | 2.5 | AllplanAttributes - ash_lichte Raumhöhe: 2.500000; OKFF: 0; RoomName: Freizeit / Club
PVC Bahnenware Holzoptik | WUN-H2-E01-059 | FLOORING | Ku1 0.15 m | 1166Bfl0000034128/01 | m² | Bodenbelagsarbeiten | 1 | 0.15 | 0 | 1 | Bodenfläche | Ku1 | 0 | 0 | NEW | AllplanAttributes - Bezeichnung: PVC Bahnenware Holzoptik; Raumnr. Bauherr: 2.11_A2_02; ash B_Aufbau: B9; ash B_Rutschhemmung: R9
 | WUN-H2-E01-059 | CLADDING | 49 0.001 m | 1166Sfl0000666650/01 | m² | Maler- und Lackierarbeiten | 1 | 0.001 | 0 | 1 | Seitenfläche | 49 | 150 | 3150 | NEW
Gipsfaserplatten 2-lagig (BSK) | WUN-H2-E01-056 | CEILING | layer 0.036 m | 1166Dfl0000232253/01 | m² | Trockenbauarbeiten | 1 | 0.036 | 0 | 1 | Deckenfläche |  | 0 | 0 | NEW | 2.5 | AllplanAttributes - Bezeichnung: Gipsfaserplatten 2-lagig (BSK); RoomName: Gespräch
Gipsfaserplatten 2-lagig (BSK) | WUN-H2-E01-056 | CEILING | Installationshöhe 0.714 m | 1166Dfl0000232253/02 | m² | Trockenbauarbeiten | 2 | 0.714 | 0 | 1 | Bekleidung | Installationshöhe | 0 | 0 | NEW | 2.5 | AllplanAttributes - ash_lichte Raumhöhe: 2.500000; OKFF: 0; RoomName: Gespräch
Gipsfaserplatten 2-lagig (BSK) | WUN-H2-E01-056 | CEILING | Aa 0.15 m | 1166Dfl0000232253/03 | m² | Trockenbauarbeiten | 3 | 0.15 | 0 | 1 | Bekleidung | Aa | 0 | 0 | NEW | 2.5 | AllplanAttributes - ash_lichte Raumhöhe: 2.500000; OKFF: 0; RoomName: Gespräch; Pset_CoveringCommon - AcousticRating: -
Gipsfaserplatten 2-lagig (BSK) | WUN-H2-E01-056 | CEILING | D1 0.001 m | 1166Dfl0000232253/04 | m² | Maler- und Lackierarbeiten | 4 | 0.001 | 0 | 1 | Bekleidung | D1 | 0 | 0 | NEW | 2.5 | AllplanAttributes - ash_lichte Raumhöhe: 2.500000; OKFF: 0; RoomName: Gespräch
Gipsfaserplatten 2-lagig (BSK) | WUN-H2-E01-056 | CEILING | layer 0.036 m | 1166Dfl0000034100/01 | m² | Trockenbauarbeiten | 1 | 0.036 | 0 | 1 | Deckenfläche |  | 0 | 0 | NEW | 2.5 | AllplanAttributes - Bezeichnung: Gipsfaserplatten 2-lagig (BSK); RoomName: Gespräch
Gipsfaserplatten 2-lagig (BSK) | WUN-H2-E01-056 | CEILING | Installationshöhe 0.714 m | 1166Dfl0000034100/02 | m² | Trockenbauarbeiten | 2 | 0.714 | 0 | 1 | Bekleidung | Installationshöhe | 0 | 0 | NEW | 2.5 | AllplanAttributes - ash_lichte Raumhöhe: 2.500000; OKFF: 0; RoomName: Gespräch
Gipsfaserplatten 2-lagig (BSK) | WUN-H2-E01-056 | CEILING | A1 0.15 m | 1166Dfl0000034100/03 | m² | Trockenbauarbeiten | 3 | 0.15 | 0 | 1 | Bekleidung | A1 | 0 | 0 | NEW | 2.5 | AllplanAttributes - ash_lichte Raumhöhe: 2.500000; OKFF: 0; RoomName: Gespräch; Pset_CoveringCommon - AcousticRating: -
Gipsfaserplatten 2-lagig (BSK) | WUN-H2-E01-056 | CEILING | D1 0.001 m | 1166Dfl0000034100/04 | m² | Maler- und Lackierarbeiten | 4 | 0.001 | 0 | 1 | Bekleidung | D1 | 0 | 0 | NEW | 2.5 | AllplanAttributes - ash_lichte Raumhöhe: 2.500000; OKFF: 0; RoomName: Gespräch
PVC Bahnenware Holzoptik | WUN-H2-E01-056 | FLOORING | Ku1 0.15 m | 1166Bfl0000034089/01 | m² | Bodenbelagsarbeiten | 1 | 0.15 | 0 | 1 | Bodenfläche | Ku1 | 0 | 0 | NEW | AllplanAttributes - Bezeichnung: PVC Bahnenware Holzoptik; Raumnr. Bauherr: 2.11_A2_02; ash B_Aufbau: B9; ash B_Rutschhemmung: R9
 | WUN-H2-E01-056 | CLADDING | 49 0.001 m | 1166Sfl0000666651/01 | m² | Maler- und Lackierarbeiten | 1 | 0.001 | 0 | 1 | Seitenfläche | 49 | 150 | 3150 | NEW
Gipsfaserplatten 2-lagig (BSK) | WUN-H2-E01-066 | CEILING | layer 0.036 m | 1166Dfl0000034250/01 | m² | Trockenbauarbeiten | 1 | 0.036 | 0 | 1 | Deckenfläche |  | 0 | 0 | NEW | 2.5 | AllplanAttributes - Bezeichnung: Gipsfaserplatten 2-lagig (BSK); RoomName: Ruheraum
Gipsfaserplatten 2-lagig (BSK) | WUN-H2-E01-066 | CEILING | Installationshöhe 0.764 m | 1166Dfl0000034250/02 | m² | Trockenbauarbeiten | 2 | 0.764 | 0 | 1 | Bekleidung | Installationshöhe | 0 | 0 | NEW | 2.5 | AllplanAttributes - ash_lichte Raumhöhe: 2.500000; OKFF: 0; RoomName: Ruheraum
Kühldecke glatt | WUN-H2-E01-066 | CEILING | H7a 0.1 m | 1166Dfl0000034250/03 | m² | Trockenbauarbeiten | 3 | 0.1 | 0 | 1 | Bekleidung | H7a | 0 | 0 | NEW | 2.5 | AllplanAttributes - Bezeichnung: Kühldecke glatt; ash_lichte Raumhöhe: 2.500000; OKFF: 0; RoomName: Ruheraum; Pset_CoveringCommon - AcousticRating: -
Gipsfaserplatten 2-lagig (BSK) | WUN-H2-E01-066 | CEILING | D1 0.001 m | 1166Dfl0000034250/04 | m² | Maler- und Lackierarbeiten | 4 | 0.001 | 0 | 1 | Bekleidung | D1 | 0 | 0 | NEW | 2.5 | AllplanAttributes - ash_lichte Raumhöhe: 2.500000; OKFF: 0; RoomName: Ruheraum
Gipsfaserplatten 2-lagig (BSK) | WUN-H2-E01-066 | CEILING | layer 0.036 m | 1166Dfl0000446820/01 | m² | Trockenbauarbeiten | 1 | 0.036 | 0 | 1 | Deckenfläche |  | 0 | 0 | NEW | 2.5 | AllplanAttributes - Bezeichnung: Gipsfaserplatten 2-lagig (BSK); RoomName: Ruheraum
Gipsfaserplatten 2-lagig (BSK) | WUN-H2-E01-066 | CEILING | Installationshöhe 0.764 m | 1166Dfl0000446820/02 | m² | Trockenbauarbeiten | 2 | 0.764 | 0 | 1 | Bekleidung | Installationshöhe | 0 | 0 | NEW | 2.5 | AllplanAttributes - ash_lichte Raumhöhe: 2.500000; OKFF: 0; RoomName: Ruheraum
Kühldecke gelocht | WUN-H2-E01-066 | CEILING | H7b 0.1 m | 1166Dfl0000446820/03 | m² | Trockenbauarbeiten | 3 | 0.1 | 0 | 1 | Bekleidung | H7b | 0 | 0 | NEW | 2.5 | AllplanAttributes - Bezeichnung: Kühldecke gelocht; ash_lichte Raumhöhe: 2.500000; OKFF: 0; RoomName: Ruheraum; Pset_CoveringCommon - AcousticRating: -
Gipsfaserplatten 2-lagig (BSK) | WUN-H2-E01-066 | CEILING | D1 0.001 m | 1166Dfl0000446820/04 | m² | Maler- und Lackierarbeiten | 4 | 0.001 | 0 | 1 | Bekleidung | D1 | 0 | 0 | NEW | 2.5 | AllplanAttributes - ash_lichte Raumhöhe: 2.500000; OKFF: 0; RoomName: Ruheraum
PVC Bahnenware Holzoptik | WUN-H2-E01-066 | FLOORING | Ku1 0.15 m | 1166Bfl0000034239/01 | m² | Bodenbelagsarbeiten | 1 | 0.15 | 0 | 1 | Bodenfläche | Ku1 | 0 | 0 | NEW | AllplanAttributes - Bezeichnung: PVC Bahnenware Holzoptik; Raumnr. Bauherr: 2.11_A2_02; ash B_Aufbau: B9; ash B_Rutschhemmung: R9
 | WUN-H2-E01-066 | CLADDING | 49 0.001 m | 1166Sfl0000666653/01 | m² | Maler- und Lackierarbeiten | 1 | 0.001 | 0 | 1 | Seitenfläche | 49 | 150 | 3150 | NEW
Gipsfaserplatten 2-lagig (BSK) | WUN-H2-E01-064a | CEILING | layer 0.036 m | 1166Dfl0000445660/01 | m² | Trockenbauarbeiten | 1 | 0.036 | 0 | 1 | Deckenfläche |  | 0 | 0 | NEW | 2.5 | AllplanAttributes - Bezeichnung: Gipsfaserplatten 2-lagig (BSK); RoomName: Ruheraum
Gipsfaserplatten 2-lagig (BSK) | WUN-H2-E01-064a | CEILING | Installationshöhe 0.764 m | 1166Dfl0000445660/02 | m² | Trockenbauarbeiten | 2 | 0.764 | 0 | 1 | Bekleidung | Installationshöhe | 0 | 0 | NEW | 2.5 | AllplanAttributes - ash_lichte Raumhöhe: 2.500000; OKFF: 0; RoomName: Ruheraum
Kühldecke gelocht | WUN-H2-E01-064a | CEILING | H7b 0.1 m | 1166Dfl0000445660/03 | m² | Trockenbauarbeiten | 3 | 0.1 | 0 | 1 | Bekleidung | H7b | 0 | 0 | NEW | 2.5 | AllplanAttributes - Bezeichnung: Kühldecke gelocht; ash_lichte Raumhöhe: 2.500000; OKFF: 0; RoomName: Ruheraum; Pset_CoveringCommon - AcousticRating: -
Gipsfaserplatten 2-lagig (BSK) | WUN-H2-E01-064a | CEILING | D1 0.001 m | 1166Dfl0000445660/04 | m² | Maler- und Lackierarbeiten | 4 | 0.001 | 0 | 1 | Bekleidung | D1 | 0 | 0 | NEW | 2.5 | AllplanAttributes - ash_lichte Raumhöhe: 2.500000; OKFF: 0; RoomName: Ruheraum
Gipsfaserplatten 2-lagig (BSK) | WUN-H2-E01-064a | CEILING | layer 0.036 m | 1166Dfl0000042439/01 | m² | Trockenbauarbeiten | 1 | 0.036 | 0 | 1 | Deckenfläche |  | 0 | 0 | NEW | 2.5 | AllplanAttributes - Bezeichnung: Gipsfaserplatten 2-lagig (BSK); RoomName: Krisenzimmer 1-Bett
Gipsfaserplatten 2-lagig (BSK) | WUN-H2-E01-064a | CEILING | Installationshöhe 0.764 m | 1166Dfl0000042439/02 | m² | Trockenbauarbeiten | 2 | 0.764 | 0 | 1 | Bekleidung | Installationshöhe | 0 | 0 | NEW | 2.5 | AllplanAttributes - ash_lichte Raumhöhe: 2.500000; OKFF: 0; RoomName: Krisenzimmer 1-Bett
Kühldecke glatt | WUN-H2-E01-064a | CEILING | H7a 0.1 m | 1166Dfl0000042439/03 | m² | Trockenbauarbeiten | 3 | 0.1 | 0 | 1 | Bekleidung | H7a | 0 | 0 | NEW | 2.5 | AllplanAttributes - Bezeichnung: Kühldecke glatt; ash_lichte Raumhöhe: 2.500000; OKFF: 0; RoomName: Krisenzimmer 1-Bett; Pset_CoveringCommon - AcousticRating: -
Gipsfaserplatten 2-lagig (BSK) | WUN-H2-E01-064a | CEILING | D1 0.001 m | 1166Dfl0000042439/04 | m² | Maler- und Lackierarbeiten | 4 | 0.001 | 0 | 1 | Bekleidung | D1 | 0 | 0 | NEW | 2.5 | AllplanAttributes - ash_lichte Raumhöhe: 2.500000; OKFF: 0; RoomName: Krisenzimmer 1-Bett
PVC Bahnenware Holzoptik | WUN-H2-E01-064a | FLOORING | Ku1 0.15 m | 1166Bfl0000042117/01 | m² | Bodenbelagsarbeiten | 1 | 0.15 | 0 | 1 | Bodenfläche | Ku1 | 0 | 0 | NEW | AllplanAttributes - Bezeichnung: PVC Bahnenware Holzoptik; Raumnr. Bauherr: 2.11_A2_02; ash B_Aufbau: B9; ash B_Rutschhemmung: R9
 | WUN-H2-E01-064a | CLADDING | 49 0.001 m | 1166Sfl0000666654/01 | m² | Maler- und Lackierarbeiten | 1 | 0.001 | 0 | 1 | Seitenfläche | 49 | 150 | 3150 | NEW
Gipsfaserplatten 2-lagig (BSK) | WUN-H2-E01-012a | CEILING | layer 0.036 m | 1166Dfl0000042148/01 | m² | Trockenbauarbeiten | 1 | 0.036 | 0 | 1 | Deckenfläche |  | 0 | 0 | NEW | 2.5 | AllplanAttributes - Bezeichnung: Gipsfaserplatten 2-lagig (BSK); RoomName: Krisenzimmer 1-Bett
Gipsfaserplatten 2-lagig (BSK) | WUN-H2-E01-012a | CEILING | Installationshöhe 0.764 m | 1166Dfl0000042148/02 | m² | Trockenbauarbeiten | 2 | 0.764 | 0 | 1 | Bekleidung | Installationshöhe | 0 | 0 | NEW | 2.5 | AllplanAttributes - ash_lichte Raumhöhe: 2.500000; OKFF: 0; RoomName: Krisenzimmer 1-Bett
Kühldecke glatt | WUN-H2-E01-012a | CEILING | H7a 0.1 m | 1166Dfl0000042148/03 | m² | Trockenbauarbeiten | 3 | 0.1 | 0 | 1 | Bekleidung | H7a | 0 | 0 | NEW | 2.5 | AllplanAttributes - Bezeichnung: Kühldecke glatt; ash_lichte Raumhöhe: 2.500000; OKFF: 0; RoomName: Krisenzimmer 1-Bett; Pset_CoveringCommon - AcousticRating: -
Gipsfaserplatten 2-lagig (BSK) | WUN-H2-E01-012a | CEILING | D1 0.001 m | 1166Dfl0000042148/04 | m² | Maler- und Lackierarbeiten | 4 | 0.001 | 0 | 1 | Bekleidung | D1 | 0 | 0 | NEW | 2.5 | AllplanAttributes - ash_lichte Raumhöhe: 2.500000; OKFF: 0; RoomName: Krisenzimmer 1-Bett
Gipsfaserplatten 2-lagig (BSK) | WUN-H2-E01-012a | CEILING | layer 0.036 m | 1166Dfl0000445080/01 | m² | Trockenbauarbeiten | 1 | 0.036 | 0 | 1 | Deckenfläche |  | 0 | 0 | NEW | 2.5 | AllplanAttributes - Bezeichnung: Gipsfaserplatten 2-lagig (BSK); RoomName: Ruheraum
Gipsfaserplatten 2-lagig (BSK) | WUN-H2-E01-012a | CEILING | Installationshöhe 0.764 m | 1166Dfl0000445080/02 | m² | Trockenbauarbeiten | 2 | 0.764 | 0 | 1 | Bekleidung | Installationshöhe | 0 | 0 | NEW | 2.5 | AllplanAttributes - ash_lichte Raumhöhe: 2.500000; OKFF: 0; RoomName: Ruheraum
Kühldecke gelocht | WUN-H2-E01-012a | CEILING | H7b 0.1 m | 1166Dfl0000445080/03 | m² | Trockenbauarbeiten | 3 | 0.1 | 0 | 1 | Bekleidung | H7b | 0 | 0 | NEW | 2.5 | AllplanAttributes - Bezeichnung: Kühldecke gelocht; ash_lichte Raumhöhe: 2.500000; OKFF: 0; RoomName: Ruheraum; Pset_CoveringCommon - AcousticRating: -
Gipsfaserplatten 2-lagig (BSK) | WUN-H2-E01-012a | CEILING | D1 0.001 m | 1166Dfl0000445080/04 | m² | Maler- und Lackierarbeiten | 4 | 0.001 | 0 | 1 | Bekleidung | D1 | 0 | 0 | NEW | 2.5 | AllplanAttributes - ash_lichte Raumhöhe: 2.500000; OKFF: 0; RoomName: Ruheraum
PVC Bahnenware Holzoptik | WUN-H2-E01-012a | FLOORING | Ku1 0.15 m | 1166Bfl0000033230/01 | m² | Bodenbelagsarbeiten | 1 | 0.15 | 0 | 1 | Bodenfläche | Ku1 | 0 | 0 | NEW | AllplanAttributes - Bezeichnung: PVC Bahnenware Holzoptik; Raumnr. Bauherr: 2.11_A2_02; ash B_Aufbau: B9; ash B_Rutschhemmung: R9
 | WUN-H2-E01-012a | CLADDING | 49 0.001 m | 1166Sfl0000666655/01 | m² | Maler- und Lackierarbeiten | 1 | 0.001 | 0 | 1 | Seitenfläche | 49 | 150 | 3150 | NEW
Gipsfaserplatten 2-lagig (BSK) | WUN-H2-E01-085 | CEILING | layer 0.036 m | 1166Dfl0000034344/01 | m² | Trockenbauarbeiten | 1 | 0.036 | 0 | 1 | Deckenfläche |  | 0 | 0 | NEW | 2.5 | AllplanAttributes - Bezeichnung: Gipsfaserplatten 2-lagig (BSK); RoomName: Sprechzimmer
Gipsfaserplatten 2-lagig (BSK) | WUN-H2-E01-085 | CEILING | Installationshöhe 0.714 m | 1166Dfl0000034344/02 | m² | Trockenbauarbeiten | 2 | 0.714 | 0 | 1 | Bekleidung | Installationshöhe | 0 | 0 | NEW | 2.5 | AllplanAttributes - ash_lichte Raumhöhe: 2.500000; OKFF: 0; RoomName: Sprechzimmer
Gipsfaserplatten 2-lagig (BSK) | WUN-H2-E01-085 | CEILING | A1 0.15 m | 1166Dfl0000034344/03 | m² | Trockenbauarbeiten | 3 | 0.15 | 0 | 1 | Bekleidung | A1 | 0 | 0 | NEW | 2.5 | AllplanAttributes - ash_lichte Raumhöhe: 2.500000; OKFF: 0; RoomName: Sprechzimmer; Pset_CoveringCommon - AcousticRating: -
Gipsfaserplatten 2-lagig (BSK) | WUN-H2-E01-085 | CEILING | D1 0.001 m | 1166Dfl0000034344/04 | m² | Maler- und Lackierarbeiten | 4 | 0.001 | 0 | 1 | Bekleidung | D1 | 0 | 0 | NEW | 2.5 | AllplanAttributes - ash_lichte Raumhöhe: 2.500000; OKFF: 0; RoomName: Sprechzimmer
Gipsfaserplatten 2-lagig (BSK) | WUN-H2-E01-085 | CEILING | layer 0.036 m | 1166Dfl0000236640/01 | m² | Trockenbauarbeiten | 1 | 0.036 | 0 | 1 | Deckenfläche |  | 0 | 0 | NEW | 2.5 | AllplanAttributes - Bezeichnung: Gipsfaserplatten 2-lagig (BSK); RoomName: Sprechzimmer
Gipsfaserplatten 2-lagig (BSK) | WUN-H2-E01-085 | CEILING | Installationshöhe 0.714 m | 1166Dfl0000236640/02 | m² | Trockenbauarbeiten | 2 | 0.714 | 0 | 1 | Bekleidung | Installationshöhe | 0 | 0 | NEW | 2.5 | AllplanAttributes - ash_lichte Raumhöhe: 2.500000; OKFF: 0; RoomName: Sprechzimmer
Gipsfaserplatten 2-lagig (BSK) | WUN-H2-E01-085 | CEILING | Aa 0.15 m | 1166Dfl0000236640/03 | m² | Trockenbauarbeiten | 3 | 0.15 | 0 | 1 | Bekleidung | Aa | 0 | 0 | NEW | 2.5 | AllplanAttributes - ash_lichte Raumhöhe: 2.500000; OKFF: 0; RoomName: Sprechzimmer; Pset_CoveringCommon - AcousticRating: -
Gipsfaserplatten 2-lagig (BSK) | WUN-H2-E01-085 | CEILING | D1 0.001 m | 1166Dfl0000236640/04 | m² | Maler- und Lackierarbeiten | 4 | 0.001 | 0 | 1 | Bekleidung | D1 | 0 | 0 | NEW | 2.5 | AllplanAttributes - ash_lichte Raumhöhe: 2.500000; OKFF: 0; RoomName: Sprechzimmer
PVC Bahnenware Holzoptik | WUN-H2-E01-085 | FLOORING | Ku1 0.15 m | 1166Bfl0000034333/01 | m² | Bodenbelagsarbeiten | 1 | 0.15 | 0 | 1 | Bodenfläche | Ku1 | 0 | 0 | NEW | AllplanAttributes - Bezeichnung: PVC Bahnenware Holzoptik; Raumnr. Bauherr: 2.11_A2_02; ash B_Aufbau: B9; ash B_Rutschhemmung: R9
 | WUN-H2-E01-085 | CLADDING | 49 0.001 m | 1166Sfl0000666656/01 | m² | Maler- und Lackierarbeiten | 1 | 0.001 | 0 | 1 | Seitenfläche | 49 | 150 | 3150 | NEW
Gipsfaserplatten 2-lagig (BSK) | WUN-H2-E01-084 | CEILING | layer 0.036 m | 1166Dfl0000237227/01 | m² | Trockenbauarbeiten | 1 | 0.036 | 0 | 1 | Deckenfläche |  | 0 | 0 | NEW | 2.5 | AllplanAttributes - Bezeichnung: Gipsfaserplatten 2-lagig (BSK); RoomName: Pause Personal
Gipsfaserplatten 2-lagig (BSK) | WUN-H2-E01-084 | CEILING | Installationshöhe 0.714 m | 1166Dfl0000237227/02 | m² | Trockenbauarbeiten | 2 | 0.714 | 0 | 1 | Bekleidung | Installationshöhe | 0 | 0 | NEW | 2.5 | AllplanAttributes - ash_lichte Raumhöhe: 2.500000; OKFF: 0; RoomName: Pause Personal
Gipsfaserplatten 2-lagig (BSK) | WUN-H2-E01-084 | CEILING | Aa 0.15 m | 1166Dfl0000237227/03 | m² | Trockenbauarbeiten | 3 | 0.15 | 0 | 1 | Bekleidung | Aa | 0 | 0 | NEW | 2.5 | AllplanAttributes - ash_lichte Raumhöhe: 2.500000; OKFF: 0; RoomName: Pause Personal; Pset_CoveringCommon - AcousticRating: -
Gipsfaserplatten 2-lagig (BSK) | WUN-H2-E01-084 | CEILING | D1 0.001 m | 1166Dfl0000237227/04 | m² | Maler- und Lackierarbeiten | 4 | 0.001 | 0 | 1 | Bekleidung | D1 | 0 | 0 | NEW | 2.5 | AllplanAttributes - ash_lichte Raumhöhe: 2.500000; OKFF: 0; RoomName: Pause Personal
Gipsfaserplatten 2-lagig (BSK) | WUN-H2-E01-084 | CEILING | layer 0.036 m | 1166Dfl0000034720/01 | m² | Trockenbauarbeiten | 1 | 0.036 | 0 | 1 | Deckenfläche |  | 0 | 0 | NEW | 2.5 | AllplanAttributes - Bezeichnung: Gipsfaserplatten 2-lagig (BSK); RoomName: Pause Personal
Gipsfaserplatten 2-lagig (BSK) | WUN-H2-E01-084 | CEILING | Installationshöhe 0.714 m | 1166Dfl0000034720/02 | m² | Trockenbauarbeiten | 2 | 0.714 | 0 | 1 | Bekleidung | Installationshöhe | 0 | 0 | NEW | 2.5 | AllplanAttributes - ash_lichte Raumhöhe: 2.500000; OKFF: 0; RoomName: Pause Personal
Gipsfaserplatten 2-lagig (BSK) | WUN-H2-E01-084 | CEILING | A1 0.15 m | 1166Dfl0000034720/03 | m² | Trockenbauarbeiten | 3 | 0.15 | 0 | 1 | Bekleidung | A1 | 0 | 0 | NEW | 2.5 | AllplanAttributes - ash_lichte Raumhöhe: 2.500000; OKFF: 0; RoomName: Pause Personal; Pset_CoveringCommon - AcousticRating: -
Gipsfaserplatten 2-lagig (BSK) | WUN-H2-E01-084 | CEILING | D1 0.001 m | 1166Dfl0000034720/04 | m² | Maler- und Lackierarbeiten | 4 | 0.001 | 0 | 1 | Bekleidung | D1 | 0 | 0 | NEW | 2.5 | AllplanAttributes - ash_lichte Raumhöhe: 2.500000; OKFF: 0; RoomName: Pause Personal
PVC Bahnenware Holzoptik | WUN-H2-E01-084 | FLOORING | Ku1 0.15 m | 1166Bfl0000034714/01 | m² | Bodenbelagsarbeiten | 1 | 0.15 | 0 | 1 | Bodenfläche | Ku1 | 0 | 0 | NEW | AllplanAttributes - Bezeichnung: PVC Bahnenware Holzoptik; Raumnr. Bauherr: 2.11_A2_02; ash B_Aufbau: B9; ash B_Rutschhemmung: R9
 | WUN-H2-E01-084 | CLADDING | 49 0.001 m | 1166Sfl0000666657/01 | m² | Maler- und Lackierarbeiten | 1 | 0.001 | 0 | 1 | Seitenfläche | 49 | 150 | 3150 | NEW
Gipsfaserplatten 2-lagig (BSK) | WUN-H2-E01-086 | CEILING | layer 0.036 m | 1166Dfl0000236055/01 | m² | Trockenbauarbeiten | 1 | 0.036 | 0 | 1 | Deckenfläche |  | 0 | 0 | NEW | 2.5 | AllplanAttributes - Bezeichnung: Gipsfaserplatten 2-lagig (BSK); RoomName: Sprechzimmer
Gipsfaserplatten 2-lagig (BSK) | WUN-H2-E01-086 | CEILING | Installationshöhe 0.714 m | 1166Dfl0000236055/02 | m² | Trockenbauarbeiten | 2 | 0.714 | 0 | 1 | Bekleidung | Installationshöhe | 0 | 0 | NEW | 2.5 | AllplanAttributes - ash_lichte Raumhöhe: 2.500000; OKFF: 0; RoomName: Sprechzimmer
Gipsfaserplatten 2-lagig (BSK) | WUN-H2-E01-086 | CEILING | Aa 0.15 m | 1166Dfl0000236055/03 | m² | Trockenbauarbeiten | 3 | 0.15 | 0 | 1 | Bekleidung | Aa | 0 | 0 | NEW | 2.5 | AllplanAttributes - ash_lichte Raumhöhe: 2.500000; OKFF: 0; RoomName: Sprechzimmer; Pset_CoveringCommon - AcousticRating: -
Gipsfaserplatten 2-lagig (BSK) | WUN-H2-E01-086 | CEILING | D1 0.001 m | 1166Dfl0000236055/04 | m² | Maler- und Lackierarbeiten | 4 | 0.001 | 0 | 1 | Bekleidung | D1 | 0 | 0 | NEW | 2.5 | AllplanAttributes - ash_lichte Raumhöhe: 2.500000; OKFF: 0; RoomName: Sprechzimmer
Gipsfaserplatten 2-lagig (BSK) | WUN-H2-E01-086 | CEILING | layer 0.036 m | 1166Dfl0000235759/01 | m² | Trockenbauarbeiten | 1 | 0.036 | 0 | 1 | Deckenfläche |  | 0 | 0 | NEW | 2.5 | AllplanAttributes - Bezeichnung: Gipsfaserplatten 2-lagig (BSK); RoomName: Sprechzimmer
Gipsfaserplatten 2-lagig (BSK) | WUN-H2-E01-086 | CEILING | Installationshöhe 0.714 m | 1166Dfl0000235759/02 | m² | Trockenbauarbeiten | 2 | 0.714 | 0 | 1 | Bekleidung | Installationshöhe | 0 | 0 | NEW | 2.5 | AllplanAttributes - ash_lichte Raumhöhe: 2.500000; OKFF: 0; RoomName: Sprechzimmer
Gipsfaserplatten 2-lagig (BSK) | WUN-H2-E01-086 | CEILING | A1 0.15 m | 1166Dfl0000235759/03 | m² | Trockenbauarbeiten | 3 | 0.15 | 0 | 1 | Bekleidung | A1 | 0 | 0 | NEW | 2.5 | AllplanAttributes - ash_lichte Raumhöhe: 2.500000; OKFF: 0; RoomName: Sprechzimmer; Pset_CoveringCommon - AcousticRating: -
Gipsfaserplatten 2-lagig (BSK) | WUN-H2-E01-086 | CEILING | D1 0.001 m | 1166Dfl0000235759/04 | m² | Maler- und Lackierarbeiten | 4 | 0.001 | 0 | 1 | Bekleidung | D1 | 0 | 0 | NEW | 2.5 | AllplanAttributes - ash_lichte Raumhöhe: 2.500000; OKFF: 0; RoomName: Sprechzimmer
PVC Bahnenware Holzoptik | WUN-H2-E01-086 | FLOORING | Ku1 0.15 m | 1166Bfl0000034346/01 | m² | Bodenbelagsarbeiten | 1 | 0.15 | 0 | 1 | Bodenfläche | Ku1 | 0 | 0 | NEW | AllplanAttributes - Bezeichnung: PVC Bahnenware Holzoptik; Raumnr. Bauherr: 2.11_A2_02; ash B_Aufbau: B9; ash B_Rutschhemmung: R9
 | WUN-H2-E01-086 | CLADDING | 49 0.001 m | 1166Sfl0000666658/01 | m² | Maler- und Lackierarbeiten | 1 | 0.001 | 0 | 1 | Seitenfläche | 49 | 150 | 3150 | NEW
Gipsfaserplatten 2-lagig (BSK) | WUN-H2-E01-082 | CEILING | layer 0.036 m | 1166Dfl0000238397/01 | m² | Trockenbauarbeiten | 1 | 0.036 | 0 | 1 | Deckenfläche |  | 0 | 0 | NEW | 2.5 | AllplanAttributes - Bezeichnung: Gipsfaserplatten 2-lagig (BSK); RoomName: Sprechzimmer
Gipsfaserplatten 2-lagig (BSK) | WUN-H2-E01-082 | CEILING | Installationshöhe 0.714 m | 1166Dfl0000238397/02 | m² | Trockenbauarbeiten | 2 | 0.714 | 0 | 1 | Bekleidung | Installationshöhe | 0 | 0 | NEW | 2.5 | AllplanAttributes - ash_lichte Raumhöhe: 2.500000; OKFF: 0; RoomName: Sprechzimmer
Gipsfaserplatten 2-lagig (BSK) | WUN-H2-E01-082 | CEILING | Aa 0.15 m | 1166Dfl0000238397/03 | m² | Trockenbauarbeiten | 3 | 0.15 | 0 | 1 | Bekleidung | Aa | 0 | 0 | NEW | 2.5 | AllplanAttributes - ash_lichte Raumhöhe: 2.500000; OKFF: 0; RoomName: Sprechzimmer; Pset_CoveringCommon - AcousticRating: -
Gipsfaserplatten 2-lagig (BSK) | WUN-H2-E01-082 | CEILING | D1 0.001 m | 1166Dfl0000238397/04 | m² | Maler- und Lackierarbeiten | 4 | 0.001 | 0 | 1 | Bekleidung | D1 | 0 | 0 | NEW | 2.5 | AllplanAttributes - ash_lichte Raumhöhe: 2.500000; OKFF: 0; RoomName: Sprechzimmer
Gipsfaserplatten 2-lagig (BSK) | WUN-H2-E01-082 | CEILING | layer 0.036 m | 1166Dfl0000034318/01 | m² | Trockenbauarbeiten | 1 | 0.036 | 0 | 1 | Deckenfläche |  | 0 | 0 | NEW | 2.5 | AllplanAttributes - Bezeichnung: Gipsfaserplatten 2-lagig (BSK); RoomName: Sprechzimmer
Gipsfaserplatten 2-lagig (BSK) | WUN-H2-E01-082 | CEILING | Installationshöhe 0.714 m | 1166Dfl0000034318/02 | m² | Trockenbauarbeiten | 2 | 0.714 | 0 | 1 | Bekleidung | Installationshöhe | 0 | 0 | NEW | 2.5 | AllplanAttributes - ash_lichte Raumhöhe: 2.500000; OKFF: 0; RoomName: Sprechzimmer
Gipsfaserplatten 2-lagig (BSK) | WUN-H2-E01-082 | CEILING | A1 0.15 m | 1166Dfl0000034318/03 | m² | Trockenbauarbeiten | 3 | 0.15 | 0 | 1 | Bekleidung | A1 | 0 | 0 | NEW | 2.5 | AllplanAttributes - ash_lichte Raumhöhe: 2.500000; OKFF: 0; RoomName: Sprechzimmer; Pset_CoveringCommon - AcousticRating: -
Gipsfaserplatten 2-lagig (BSK) | WUN-H2-E01-082 | CEILING | D1 0.001 m | 1166Dfl0000034318/04 | m² | Maler- und Lackierarbeiten | 4 | 0.001 | 0 | 1 | Bekleidung | D1 | 0 | 0 | NEW | 2.5 | AllplanAttributes - ash_lichte Raumhöhe: 2.500000; OKFF: 0; RoomName: Sprechzimmer
PVC Bahnenware Holzoptik | WUN-H2-E01-082 | FLOORING | Ku1 0.15 m | 1166Bfl0000034307/01 | m² | Bodenbelagsarbeiten | 1 | 0.15 | 0 | 1 | Bodenfläche | Ku1 | 0 | 0 | NEW | AllplanAttributes - Bezeichnung: PVC Bahnenware Holzoptik; Raumnr. Bauherr: 2.11_A2_02; ash B_Aufbau: B9; ash B_Rutschhemmung: R9
 | WUN-H2-E01-082 | CLADDING | 49 0.001 m | 1166Sfl0000666659/01 | m² | Maler- und Lackierarbeiten | 1 | 0.001 | 0 | 1 | Seitenfläche | 49 | 150 | 3150 | NEW
Gipsfaserplatten 2-lagig (BSK) | WUN-H2-E01-083 | CEILING | layer 0.036 m | 1166Dfl0000237812/01 | m² | Trockenbauarbeiten | 1 | 0.036 | 0 | 1 | Deckenfläche |  | 0 | 0 | NEW | 2.5 | AllplanAttributes - Bezeichnung: Gipsfaserplatten 2-lagig (BSK); RoomName: Sprechzimmer
Gipsfaserplatten 2-lagig (BSK) | WUN-H2-E01-083 | CEILING | Installationshöhe 0.714 m | 1166Dfl0000237812/02 | m² | Trockenbauarbeiten | 2 | 0.714 | 0 | 1 | Bekleidung | Installationshöhe | 0 | 0 | NEW | 2.5 | AllplanAttributes - ash_lichte Raumhöhe: 2.500000; OKFF: 0; RoomName: Sprechzimmer
Gipsfaserplatten 2-lagig (BSK) | WUN-H2-E01-083 | CEILING | Aa 0.15 m | 1166Dfl0000237812/03 | m² | Trockenbauarbeiten | 3 | 0.15 | 0 | 1 | Bekleidung | Aa | 0 | 0 | NEW | 2.5 | AllplanAttributes - ash_lichte Raumhöhe: 2.500000; OKFF: 0; RoomName: Sprechzimmer; Pset_CoveringCommon - AcousticRating: -
Gipsfaserplatten 2-lagig (BSK) | WUN-H2-E01-083 | CEILING | D1 0.001 m | 1166Dfl0000237812/04 | m² | Maler- und Lackierarbeiten | 4 | 0.001 | 0 | 1 | Bekleidung | D1 | 0 | 0 | NEW | 2.5 | AllplanAttributes - ash_lichte Raumhöhe: 2.500000; OKFF: 0; RoomName: Sprechzimmer
Gipsfaserplatten 2-lagig (BSK) | WUN-H2-E01-083 | CEILING | layer 0.036 m | 1166Dfl0000034331/01 | m² | Trockenbauarbeiten | 1 | 0.036 | 0 | 1 | Deckenfläche |  | 0 | 0 | NEW | 2.5 | AllplanAttributes - Bezeichnung: Gipsfaserplatten 2-lagig (BSK); RoomName: Sprechzimmer
Gipsfaserplatten 2-lagig (BSK) | WUN-H2-E01-083 | CEILING | Installationshöhe 0.714 m | 1166Dfl0000034331/02 | m² | Trockenbauarbeiten | 2 | 0.714 | 0 | 1 | Bekleidung | Installationshöhe | 0 | 0 | NEW | 2.5 | AllplanAttributes - ash_lichte Raumhöhe: 2.500000; OKFF: 0; RoomName: Sprechzimmer
Gipsfaserplatten 2-lagig (BSK) | WUN-H2-E01-083 | CEILING | A1 0.15 m | 1166Dfl0000034331/03 | m² | Trockenbauarbeiten | 3 | 0.15 | 0 | 1 | Bekleidung | A1 | 0 | 0 | NEW | 2.5 | AllplanAttributes - ash_lichte Raumhöhe: 2.500000; OKFF: 0; RoomName: Sprechzimmer; Pset_CoveringCommon - AcousticRating: -
Gipsfaserplatten 2-lagig (BSK) | WUN-H2-E01-083 | CEILING | D1 0.001 m | 1166Dfl0000034331/04 | m² | Maler- und Lackierarbeiten | 4 | 0.001 | 0 | 1 | Bekleidung | D1 | 0 | 0 | NEW | 2.5 | AllplanAttributes - ash_lichte Raumhöhe: 2.500000; OKFF: 0; RoomName: Sprechzimmer
PVC Bahnenware Holzoptik | WUN-H2-E01-083 | FLOORING | Ku1 0.15 m | 1166Bfl0000034320/01 | m² | Bodenbelagsarbeiten | 1 | 0.15 | 0 | 1 | Bodenfläche | Ku1 | 0 | 0 | NEW | AllplanAttributes - Bezeichnung: PVC Bahnenware Holzoptik; Raumnr. Bauherr: 2.11_A2_02; ash B_Aufbau: B9; ash B_Rutschhemmung: R9
 | WUN-H2-E01-083 | CLADDING | 49 0.001 m | 1166Sfl0000666660/01 | m² | Maler- und Lackierarbeiten | 1 | 0.001 | 0 | 1 | Seitenfläche | 49 | 150 | 3150 | NEW
Gipsfaserplatten 2-lagig (BSK) | WUN-H2-E01-055 | CEILING | layer 0.036 m | 1166Dfl0000314603/01 | m² | Trockenbauarbeiten | 1 | 0.036 | 0 | 1 | Deckenfläche |  | 0 | 0 | NEW | 2.75 | AllplanAttributes - Bezeichnung: Gipsfaserplatten 2-lagig (BSK); RoomName: Speiseraum
Gipsfaserplatten 2-lagig (BSK) | WUN-H2-E01-055 | CEILING | Installationshöhe 0.424 m | 1166Dfl0000314603/02 | m² | Trockenbauarbeiten | 2 | 0.424 | 0 | 1 | Bekleidung | Installationshöhe | 0 | 0 | NEW | 2.75 | AllplanAttributes - ash_lichte Raumhöhe: 2.750000; OKFF: 0; RoomName: Speiseraum
Gipsfaserplatten 2-lagig (BSK) | WUN-H2-E01-055 | CEILING | A1 0.15 m | 1166Dfl0000314603/03 | m² | Trockenbauarbeiten | 3 | 0.15 | 0 | 1 | Bekleidung | A1 | 0 | 0 | NEW | 2.75 | AllplanAttributes - ash_lichte Raumhöhe: 2.750000; OKFF: 0; RoomName: Speiseraum; Pset_CoveringCommon - AcousticRating: -
Gipsfaserplatten 2-lagig (BSK) | WUN-H2-E01-055 | CEILING | D1 0.001 m | 1166Dfl0000314603/04 | m² | Maler- und Lackierarbeiten | 4 | 0.001 | 0 | 1 | Bekleidung | D1 | 0 | 0 | NEW | 2.75 | AllplanAttributes - ash_lichte Raumhöhe: 2.750000; OKFF: 0; RoomName: Speiseraum
Gipsfaserplatten 2-lagig (BSK) | WUN-H2-E01-055 | CEILING | layer 0.036 m | 1166Dfl0000315398/01 | m² | Trockenbauarbeiten | 1 | 0.036 | 0 | 1 | Deckenfläche |  | 0 | 0 | NEW | 2.75 | AllplanAttributes - Bezeichnung: Gipsfaserplatten 2-lagig (BSK); RoomName: Speiseraum
Gipsfaserplatten 2-lagig (BSK) | WUN-H2-E01-055 | CEILING | Installationshöhe 0.464 m | 1166Dfl0000315398/02 | m² | Trockenbauarbeiten | 2 | 0.464 | 0 | 1 | Bekleidung | Installationshöhe | 0 | 0 | NEW | 2.75 | AllplanAttributes - ash_lichte Raumhöhe: 2.750000; OKFF: 0; RoomName: Speiseraum
Gipsfaserplatten 2-lagig (BSK) | WUN-H2-E01-055 | CEILING | Aa 0.15 m | 1166Dfl0000315398/03 | m² | Trockenbauarbeiten | 3 | 0.15 | 0 | 1 | Bekleidung | Aa | 0 | 0 | NEW | 2.75 | AllplanAttributes - ash_lichte Raumhöhe: 2.750000; OKFF: 0; RoomName: Speiseraum; Pset_CoveringCommon - AcousticRating: -
Gipsfaserplatten 2-lagig (BSK) | WUN-H2-E01-055 | CEILING | D1 0.001 m | 1166Dfl0000315398/04 | m² | Maler- und Lackierarbeiten | 4 | 0.001 | 0 | 1 | Bekleidung | D1 | 0 | 0 | NEW | 2.75 | AllplanAttributes - ash_lichte Raumhöhe: 2.750000; OKFF: 0; RoomName: Speiseraum
Gipsfaserplatten 2-lagig (BSK) | WUN-H2-E01-055 | CEILING | layer 0.036 m | 1166Dfl0000314604/01 | m² | Trockenbauarbeiten | 1 | 0.036 | 0 | 1 | Deckenfläche |  | 0 | 0 | NEW | 2.75 | AllplanAttributes - Bezeichnung: Gipsfaserplatten 2-lagig (BSK); RoomName: Speiseraum
Gipsfaserplatten 2-lagig (BSK) | WUN-H2-E01-055 | CEILING | Installationshöhe 0.424 m | 1166Dfl0000314604/02 | m² | Trockenbauarbeiten | 2 | 0.424 | 0 | 1 | Bekleidung | Installationshöhe | 0 | 0 | NEW | 2.75 | AllplanAttributes - ash_lichte Raumhöhe: 2.750000; OKFF: 0; RoomName: Speiseraum
Gipsfaserplatten 2-lagig (BSK) | WUN-H2-E01-055 | CEILING | Aa 0.15 m | 1166Dfl0000314604/03 | m² | Trockenbauarbeiten | 3 | 0.15 | 0 | 1 | Bekleidung | Aa | 0 | 0 | NEW | 2.75 | AllplanAttributes - ash_lichte Raumhöhe: 2.750000; OKFF: 0; RoomName: Speiseraum; Pset_CoveringCommon - AcousticRating: -
Gipsfaserplatten 2-lagig (BSK) | WUN-H2-E01-055 | CEILING | D1 0.001 m | 1166Dfl0000314604/04 | m² | Maler- und Lackierarbeiten | 4 | 0.001 | 0 | 1 | Bekleidung | D1 | 0 | 0 | NEW | 2.75 | AllplanAttributes - ash_lichte Raumhöhe: 2.750000; OKFF: 0; RoomName: Speiseraum
Gipsfaserplatten 2-lagig (BSK) | WUN-H2-E01-055 | CEILING | layer 0.036 m | 1166Dfl0000315400/01 | m² | Trockenbauarbeiten | 1 | 0.036 | 0 | 1 | Deckenfläche |  | 0 | 0 | NEW | 2.75 | AllplanAttributes - Bezeichnung: Gipsfaserplatten 2-lagig (BSK); RoomName: Speiseraum
Gipsfaserplatten 2-lagig (BSK) | WUN-H2-E01-055 | CEILING | Installationshöhe 0.464 m | 1166Dfl0000315400/02 | m² | Trockenbauarbeiten | 2 | 0.464 | 0 | 1 | Bekleidung | Installationshöhe | 0 | 0 | NEW | 2.75 | AllplanAttributes - ash_lichte Raumhöhe: 2.750000; OKFF: 0; RoomName: Speiseraum
Gipsfaserplatten 2-lagig (BSK) | WUN-H2-E01-055 | CEILING | A1 0.15 m | 1166Dfl0000315400/03 | m² | Trockenbauarbeiten | 3 | 0.15 | 0 | 1 | Bekleidung | A1 | 0 | 0 | NEW | 2.75 | AllplanAttributes - ash_lichte Raumhöhe: 2.750000; OKFF: 0; RoomName: Speiseraum; Pset_CoveringCommon - AcousticRating: -
Gipsfaserplatten 2-lagig (BSK) | WUN-H2-E01-055 | CEILING | D1 0.001 m | 1166Dfl0000315400/04 | m² | Maler- und Lackierarbeiten | 4 | 0.001 | 0 | 1 | Bekleidung | D1 | 0 | 0 | NEW | 2.75 | AllplanAttributes - ash_lichte Raumhöhe: 2.750000; OKFF: 0; RoomName: Speiseraum
Gipsfaserplatten 2-lagig (BSK) | WUN-H2-E01-055 | CEILING | layer 0.036 m | 1166Dfl0000315405/01 | m² | Trockenbauarbeiten | 1 | 0.036 | 0 | 1 | Deckenfläche |  | 0 | 0 | NEW | 3.1 | AllplanAttributes - Bezeichnung: Gipsfaserplatten 2-lagig (BSK); RoomName: Speiseraum
Gipsfaserplatten 2-lagig (BSK) | WUN-H2-E01-055 | CEILING | Installationshöhe 0.124 m | 1166Dfl0000315405/02 | m² | Trockenbauarbeiten | 2 | 0.124 | 0 | 1 | Bekleidung | Installationshöhe | 0 | 0 | NEW | 3.1 | AllplanAttributes - ash_lichte Raumhöhe: 3.100000; OKFF: 0; RoomName: Speiseraum
Gipsfaserplatten 2-lagig (BSK) | WUN-H2-E01-055 | CEILING | A1 0.1 m | 1166Dfl0000315405/03 | m² | Trockenbauarbeiten | 3 | 0.1 | 0 | 1 | Bekleidung | A1 | 0 | 0 | NEW | 3.1 | AllplanAttributes - ash_lichte Raumhöhe: 3.100000; OKFF: 0; RoomName: Speiseraum; Pset_CoveringCommon - AcousticRating: -
Gipsfaserplatten 2-lagig (BSK) | WUN-H2-E01-055 | CEILING | D1 0.001 m | 1166Dfl0000315405/04 | m² | Maler- und Lackierarbeiten | 4 | 0.001 | 0 | 1 | Bekleidung | D1 | 0 | 0 | NEW | 3.1 | AllplanAttributes - ash_lichte Raumhöhe: 3.100000; OKFF: 0; RoomName: Speiseraum
PVC Bahnenware Holzoptik | WUN-H2-E01-055 | FLOORING | Ku1 0.15 m | 1166Bfl0000034076/01 | m² | Bodenbelagsarbeiten | 1 | 0.15 | 0 | 1 | Bodenfläche | Ku1 | 0 | 0 | NEW | AllplanAttributes - Bezeichnung: PVC Bahnenware Holzoptik; Raumnr. Bauherr: 2.11_A2_02; ash B_Aufbau: B9; ash B_Rutschhemmung: R9
Gipsfaserplatten 2-lagig (BSK) | WUN-H2-E01-055 | CEILING | layer 0.036 m | 1166Dfl0000034077/01 | m² | Trockenbauarbeiten | 1 | 0.036 | 0 | 1 | Deckenfläche |  | 0 | 0 | NEW | 3.1 | AllplanAttributes - Bezeichnung: Gipsfaserplatten 2-lagig (BSK); RoomName: Sprechzimmer
Gipsfaserplatten 2-lagig (BSK) | WUN-H2-E01-055 | CEILING | Installationshöhe 0.164 m | 1166Dfl0000034077/02 | m² | Trockenbauarbeiten | 2 | 0.164 | 0 | 1 | Bekleidung | Installationshöhe | 0 | 0 | NEW | 3.1 | AllplanAttributes - ash_lichte Raumhöhe: 3.100000; RoomName: Sprechzimmer; Pset_CoveringCommon - AcousticRating: -
Gipsfaserplatten 2-lagig (BSK) | WUN-H2-E01-055 | CEILING | A1 0.1 m | 1166Dfl0000034077/03 | m² | Trockenbauarbeiten | 3 | 0.1 | 0 | 1 | Bekleidung | A1 | 0 | 0 | NEW | 3.1 | AllplanAttributes - ash_lichte Raumhöhe: 3.100000; RoomName: Sprechzimmer; Pset_CoveringCommon - AcousticRating: -
Gipsfaserplatten 2-lagig (BSK) | WUN-H2-E01-055 | CEILING | D1 0.001 m | 1166Dfl0000034077/04 | m² | Maler- und Lackierarbeiten | 4 | 0.001 | 0 | 1 | Bekleidung | D1 | 0 | 0 | NEW | 3.1 | AllplanAttributes - ash_lichte Raumhöhe: 3.100000; RoomName: Sprechzimmer
 | WUN-H2-E01-055 | CLADDING | 49 0.001 m | 1166Sfl0000666665/01 | m² | Maler- und Lackierarbeiten | 1 | 0.001 | 0 | 1 | Seitenfläche | 49 | 150 | 3150 | NEW
Gipsfaserplatten 2-lagig (BSK) | WUN-H2-E01-011 | CEILING | layer 0.036 m | 1166Dfl0000033222/01 | m² | Trockenbauarbeiten | 1 | 0.036 | 0 | 1 | Deckenfläche |  | 0 | 0 | NEW | 2.5 | AllplanAttributes - Bezeichnung: Gipsfaserplatten 2-lagig (BSK); RoomName: AR rein
Gipsfaserplatten 2-lagig (BSK) | WUN-H2-E01-011 | CEILING | Installationshöhe 0.764 m | 1166Dfl0000033222/02 | m² | Trockenbauarbeiten | 2 | 0.764 | 0 | 1 | Bekleidung | Installationshöhe | 0 | 0 | NEW | 2.5 | AllplanAttributes - ash_lichte Raumhöhe: 2.500000; OKFF: 0; RoomName: AR rein
Kühldecke glatt | WUN-H2-E01-011 | CEILING | H7a 0.1 m | 1166Dfl0000033222/03 | m² | Trockenbauarbeiten | 3 | 0.1 | 0 | 1 | Bekleidung | H7a | 0 | 0 | NEW | 2.5 | AllplanAttributes - Bezeichnung: Kühldecke glatt; ash_lichte Raumhöhe: 2.500000; OKFF: 0; RoomName: AR rein; Pset_CoveringCommon - AcousticRating: -
Gipsfaserplatten 2-lagig (BSK) | WUN-H2-E01-011 | CEILING | D1 0.001 m | 1166Dfl0000033222/04 | m² | Maler- und Lackierarbeiten | 4 | 0.001 | 0 | 1 | Bekleidung | D1 | 0 | 0 | NEW | 2.5 | AllplanAttributes - ash_lichte Raumhöhe: 2.500000; OKFF: 0; RoomName: AR rein
PVC Bahnenware Uni | WUN-H2-E01-011 | FLOORING | Ku2 0.15 m | 1166Bfl0000033211/01 | m² | Bodenbelagsarbeiten | 1 | 0.15 | 0 | 1 | Bodenfläche | Ku2 | 0 | 0 | NEW | AllplanAttributes - Bezeichnung: PVC Bahnenware Uni; Raumnr. Bauherr: 2.11_A2_02; ash B_Aufbau: B9; ash B_Rutschhemmung: R9
 | WUN-H2-E01-011 | CLADDING | 49 0.001 m | 1166Sfl0000666666/01 | m² | Maler- und Lackierarbeiten | 1 | 0.001 | 0 | 1 | Seitenfläche | 49 | 150 | 3150 | NEW
Gipsfaserplatten 2-lagig (BSK) | WUN-H2-E01-065 | CEILING | layer 0.036 m | 1166Dfl0000034237/01 | m² | Trockenbauarbeiten | 1 | 0.036 | 0 | 1 | Deckenfläche |  | 0 | 0 | NEW | 2.5 | AllplanAttributes - Bezeichnung: Gipsfaserplatten 2-lagig (BSK); RoomName: AR rein
Gipsfaserplatten 2-lagig (BSK) | WUN-H2-E01-065 | CEILING | Installationshöhe 0.764 m | 1166Dfl0000034237/02 | m² | Trockenbauarbeiten | 2 | 0.764 | 0 | 1 | Bekleidung | Installationshöhe | 0 | 0 | NEW | 2.5 | AllplanAttributes - ash_lichte Raumhöhe: 2.500000; OKFF: 0; RoomName: AR rein
Kühldecke glatt | WUN-H2-E01-065 | CEILING | H7a 0.1 m | 1166Dfl0000034237/03 | m² | Trockenbauarbeiten | 3 | 0.1 | 0 | 1 | Bekleidung | H7a | 0 | 0 | NEW | 2.5 | AllplanAttributes - Bezeichnung: Kühldecke glatt; ash_lichte Raumhöhe: 2.500000; OKFF: 0; RoomName: AR rein; Pset_CoveringCommon - AcousticRating: -
Gipsfaserplatten 2-lagig (BSK) | WUN-H2-E01-065 | CEILING | D1 0.001 m | 1166Dfl0000034237/04 | m² | Maler- und Lackierarbeiten | 4 | 0.001 | 0 | 1 | Bekleidung | D1 | 0 | 0 | NEW | 2.5 | AllplanAttributes - ash_lichte Raumhöhe: 2.500000; OKFF: 0; RoomName: AR rein
PVC Bahnenware Uni | WUN-H2-E01-065 | FLOORING | Ku2 0.15 m | 1166Bfl0000034226/01 | m² | Bodenbelagsarbeiten | 1 | 0.15 | 0 | 1 | Bodenfläche | Ku2 | 0 | 0 | NEW | AllplanAttributes - Bezeichnung: PVC Bahnenware Uni; Raumnr. Bauherr: 2.11_A2_02; ash B_Aufbau: B9; ash B_Rutschhemmung: R9
 | WUN-H2-E01-065 | CLADDING | 49 0.001 m | 1166Sfl0000666667/01 | m² | Maler- und Lackierarbeiten | 1 | 0.001 | 0 | 1 | Seitenfläche | 49 | 150 | 3150 | NEW
Gipsfaserplatten 2-lagig (BSK) | WUN-H2-E01-048 | CEILING | layer 0.036 m | 1166Dfl0000033794/01 | m² | Trockenbauarbeiten | 1 | 0.036 | 0 | 1 | Deckenfläche |  | 0 | 0 | NEW | 2.5 | AllplanAttributes - Bezeichnung: Gipsfaserplatten 2-lagig (BSK); RoomName: Stationsküche
Gipsfaserplatten 2-lagig (BSK) | WUN-H2-E01-048 | CEILING | Installationshöhe 0.724 m | 1166Dfl0000033794/02 | m² | Trockenbauarbeiten | 2 | 0.724 | 0 | 1 | Bekleidung | Installationshöhe | 0 | 0 | NEW | 2.5 | AllplanAttributes - ash_lichte Raumhöhe: 2.500000; OKFF: 0; RoomName: Stationsküche
Gipsfaserplatten 2-lagig (BSK) | WUN-H2-E01-048 | CEILING | A1 0.1 m | 1166Dfl0000033794/03 | m² | Trockenbauarbeiten | 3 | 0.1 | 0 | 1 | Bekleidung | A1 | 0 | 0 | NEW | 2.5 | AllplanAttributes - ash_lichte Raumhöhe: 2.500000; OKFF: 0; RoomName: Stationsküche; Pset_CoveringCommon - AcousticRating: -
Gipsfaserplatten 2-lagig (BSK) | WUN-H2-E01-048 | CEILING | D1 0.001 m | 1166Dfl0000033794/04 | m² | Maler- und Lackierarbeiten | 4 | 0.001 | 0 | 1 | Bekleidung | D1 | 0 | 0 | NEW | 2.5 | AllplanAttributes - ash_lichte Raumhöhe: 2.500000; OKFF: 0; RoomName: Stationsküche
PVC Bahnenware Holzoptik | WUN-H2-E01-048 | FLOORING | Ku1 0.15 m | 1166Bfl0000033783/01 | m² | Bodenbelagsarbeiten | 1 | 0.15 | 0 | 1 | Bodenfläche | Ku1 | 0 | 0 | NEW | AllplanAttributes - Bezeichnung: PVC Bahnenware Holzoptik; Raumnr. Bauherr: 2.11_A2_02; ash B_Aufbau: B9; ash B_Rutschhemmung: R9
Gipsfaserplatten 2-lagig (BSK) | WUN-H2-E01-048 | CEILING | layer 0.036 m | 1166Dfl0000033784/01 | m² | Trockenbauarbeiten | 1 | 0.036 | 0 | 1 | Deckenfläche |  | 0 | 0 | NEW | 3.1 | AllplanAttributes - Bezeichnung: Gipsfaserplatten 2-lagig (BSK); RoomName: Sprechzimmer
Gipsfaserplatten 2-lagig (BSK) | WUN-H2-E01-048 | CEILING | Installationshöhe 0.124 m | 1166Dfl0000033784/02 | m² | Trockenbauarbeiten | 2 | 0.124 | 0 | 1 | Bekleidung | Installationshöhe | 0 | 0 | NEW | 3.1 | AllplanAttributes - ash_lichte Raumhöhe: 3.100000; RoomName: Sprechzimmer; Pset_CoveringCommon - AcousticRating: -
Gipsfaserplatten 2-lagig (BSK) | WUN-H2-E01-048 | CEILING | A1 0.1 m | 1166Dfl0000033784/03 | m² | Trockenbauarbeiten | 3 | 0.1 | 0 | 1 | Bekleidung | A1 | 0 | 0 | NEW | 3.1 | AllplanAttributes - ash_lichte Raumhöhe: 3.100000; RoomName: Sprechzimmer; Pset_CoveringCommon - AcousticRating: -
Gipsfaserplatten 2-lagig (BSK) | WUN-H2-E01-048 | CEILING | D1 0.001 m | 1166Dfl0000033784/04 | m² | Maler- und Lackierarbeiten | 4 | 0.001 | 0 | 1 | Bekleidung | D1 | 0 | 0 | NEW | 3.1 | AllplanAttributes - ash_lichte Raumhöhe: 3.100000; RoomName: Sprechzimmer
 | WUN-H2-E01-048 | CLADDING | 49 0.001 m | 1166Sfl0000666668/01 | m² | Maler- und Lackierarbeiten | 1 | 0.001 | 0 | 1 | Seitenfläche | 49 | 150 | 3150 | NEW
Gipsfaserplatten 2-lagig (BSK) | WUN-H2-E01-050 | CEILING | layer 0.036 m | 1166Dfl0000033818/01 | m² | Trockenbauarbeiten | 1 | 0.036 | 0 | 1 | Deckenfläche |  | 0 | 0 | NEW | 2.5 | AllplanAttributes - Bezeichnung: Gipsfaserplatten 2-lagig (BSK); RoomName: Stationsküche
Gipsfaserplatten 2-lagig (BSK) | WUN-H2-E01-050 | CEILING | Installationshöhe 0.724 m | 1166Dfl0000033818/02 | m² | Trockenbauarbeiten | 2 | 0.724 | 0 | 1 | Bekleidung | Installationshöhe | 0 | 0 | NEW | 2.5 | AllplanAttributes - ash_lichte Raumhöhe: 2.500000; OKFF: 0; RoomName: Stationsküche
Gipsfaserplatten 2-lagig (BSK) | WUN-H2-E01-050 | CEILING | A1 0.1 m | 1166Dfl0000033818/03 | m² | Trockenbauarbeiten | 3 | 0.1 | 0 | 1 | Bekleidung | A1 | 0 | 0 | NEW | 2.5 | AllplanAttributes - ash_lichte Raumhöhe: 2.500000; OKFF: 0; RoomName: Stationsküche; Pset_CoveringCommon - AcousticRating: -
Gipsfaserplatten 2-lagig (BSK) | WUN-H2-E01-050 | CEILING | D1 0.001 m | 1166Dfl0000033818/04 | m² | Maler- und Lackierarbeiten | 4 | 0.001 | 0 | 1 | Bekleidung | D1 | 0 | 0 | NEW | 2.5 | AllplanAttributes - ash_lichte Raumhöhe: 2.500000; OKFF: 0; RoomName: Stationsküche
PVC Bahnenware Holzoptik | WUN-H2-E01-050 | FLOORING | Ku1 0.15 m | 1166Bfl0000033807/01 | m² | Bodenbelagsarbeiten | 1 | 0.15 | 0 | 1 | Bodenfläche | Ku1 | 0 | 0 | NEW | AllplanAttributes - Bezeichnung: PVC Bahnenware Holzoptik; Raumnr. Bauherr: 2.11_A2_02; ash B_Aufbau: B9; ash B_Rutschhemmung: R9
Gipsfaserplatten 2-lagig (BSK) | WUN-H2-E01-050 | CEILING | layer 0.036 m | 1166Dfl0000033808/01 | m² | Trockenbauarbeiten | 1 | 0.036 | 0 | 1 | Deckenfläche |  | 0 | 0 | NEW | 3.1 | AllplanAttributes - Bezeichnung: Gipsfaserplatten 2-lagig (BSK); RoomName: Sprechzimmer
Gipsfaserplatten 2-lagig (BSK) | WUN-H2-E01-050 | CEILING | Installationshöhe 0.124 m | 1166Dfl0000033808/02 | m² | Trockenbauarbeiten | 2 | 0.124 | 0 | 1 | Bekleidung | Installationshöhe | 0 | 0 | NEW | 3.1 | AllplanAttributes - ash_lichte Raumhöhe: 3.100000; RoomName: Sprechzimmer; Pset_CoveringCommon - AcousticRating: -
Gipsfaserplatten 2-lagig (BSK) | WUN-H2-E01-050 | CEILING | A1 0.1 m | 1166Dfl0000033808/03 | m² | Trockenbauarbeiten | 3 | 0.1 | 0 | 1 | Bekleidung | A1 | 0 | 0 | NEW | 3.1 | AllplanAttributes - ash_lichte Raumhöhe: 3.100000; RoomName: Sprechzimmer; Pset_CoveringCommon - AcousticRating: -
Gipsfaserplatten 2-lagig (BSK) | WUN-H2-E01-050 | CEILING | D1 0.001 m | 1166Dfl0000033808/04 | m² | Maler- und Lackierarbeiten | 4 | 0.001 | 0 | 1 | Bekleidung | D1 | 0 | 0 | NEW | 3.1 | AllplanAttributes - ash_lichte Raumhöhe: 3.100000; RoomName: Sprechzimmer
 | WUN-H2-E01-050 | CLADDING | 49 0.001 m | 1166Sfl0000666669/01 | m² | Maler- und Lackierarbeiten | 1 | 0.001 | 0 | 1 | Seitenfläche | 49 | 150 | 3150 | NEW
a-sh Wandbelag | WUN-H2-E01-076 | CLADDING | 68 0.01 m | 1166Sfl0000667511/01 | m² | Maler- und Lackierarbeiten | 1 | 0.01 | 0 | 1 | Seitenfläche | 68 | 100 | 3000 | NEW | AllplanAttributes - Bezeichnung: a-sh Wandbelag; Attributset-Objekt: Covering
Fliesen | WUN-H2-E01-076 | FLOORING | Fl1 0.15 m | 1166Bfl0000034033/01 | m² | Bodenbelagsarbeiten | 1 | 0.15 | 0 | 1 | Bodenfläche | Fl1 | 0 | 0 | NEW | AllplanAttributes - Bezeichnung: Fliesen; Raumnr. Bauherr: 2.11_A2_02; ash B_Aufbau: B10; ash B_Rutschhemmung: R10
Gipsfaserplatten 2-lagig (BSK) | WUN-H2-E01-076 | CEILING | layer 0.036 m | 1166Dfl0000034032/01 | m² | Trockenbauarbeiten | 1 | 0.036 | 0 | 1 | Deckenfläche |  | 0 | 0 | NEW | 2.5 | AllplanAttributes - Bezeichnung: Gipsfaserplatten 2-lagig (BSK); RoomName: Entspannungsbad
Gipsfaserplatten 2-lagig (BSK) | WUN-H2-E01-076 | CEILING | Installationshöhe 0.764 m | 1166Dfl0000034032/02 | m² | Trockenbauarbeiten | 2 | 0.764 | 0 | 1 | Bekleidung | Installationshöhe | 0 | 0 | NEW | 2.5 | AllplanAttributes - ash_lichte Raumhöhe: 2.500000; OKFF: 0; RoomName: Entspannungsbad
Gipskarton, imprägniert | WUN-H2-E01-076 | CEILING | B 0.1 m | 1166Dfl0000034032/03 | m² | Trockenbauarbeiten | 3 | 0.1 | 0 | 1 | Bekleidung | B | 0 | 0 | NEW | 2.5 | AllplanAttributes - Bezeichnung: Gipskarton, imprägniert; ash_lichte Raumhöhe: 2.500000; OKFF: 0; RoomName: Bad mit Dusche; Pset_CoveringCommon - AcousticRating: -
Gipsfaserplatten 2-lagig (BSK) | WUN-H2-E01-076 | CEILING | D1 0.001 m | 1166Dfl0000034032/04 | m² | Maler- und Lackierarbeiten | 4 | 0.001 | 0 | 1 | Bekleidung | D1 | 0 | 0 | NEW | 2.5 | AllplanAttributes - ash_lichte Raumhöhe: 2.500000; OKFF: 0; RoomName: Entspannungsbad
 | WUN-H2-E01-076 | CLADDING | 50 0.001 m | 1166Sfl0000667580/01 | m² | Maler- und Lackierarbeiten | 1 | 0.001 | 0 | 1 | Seitenfläche | 50 | 150 | 2500 | NEW
Gipsfaserplatten 2-lagig (BSK) | WUN-H2-E01-001 | CEILING | layer 0.036 m | 1166Dfl0000218630/01 | m² | Trockenbauarbeiten | 1 | 0.036 | 0 | 1 | Deckenfläche |  | 0 | 0 | NEW | 2.5 | AllplanAttributes - Bezeichnung: Gipsfaserplatten 2-lagig (BSK); RoomName: Aufenthalt / Besucher
Gipsfaserplatten 2-lagig (BSK) | WUN-H2-E01-001 | CEILING | Installationshöhe 0.764 m | 1166Dfl0000218630/02 | m² | Trockenbauarbeiten | 2 | 0.764 | 0 | 1 | Bekleidung | Installationshöhe | 0 | 0 | NEW | 2.5 | AllplanAttributes - ash_lichte Raumhöhe: (7150-36+764+100)/1000-3.75; OKFF: 0; RoomName: Aufenthalt / Besucher
Rasterdecke | WUN-H2-E01-001 | CEILING | E3 0.1 m | 1166Dfl0000218630/03 | m² | Trockenbauarbeiten | 3 | 0.1 | 0 | 1 | Bekleidung | E3 | 0 | 0 | NEW | 2.5 | AllplanAttributes - Bezeichnung: Rasterdecke; ash_lichte Raumhöhe: (7150-36+764+100)/1000-3.75; OKFF: 0; RoomName: Aufenthalt / Besucher; Pset_CoveringCommon - AcousticRating: -
PVC Bahnenware Uni | WUN-H2-E01-001 | FLOORING | Ku2 0.15 m | 1166Bfl0000033085/01 | m² | Bodenbelagsarbeiten | 1 | 0.15 | 0 | 1 | Bodenfläche | Ku2 | 0 | 0 | NEW | AllplanAttributes - Bezeichnung: PVC Bahnenware Uni; Raumnr. Bauherr: 2.11_A2_02; ash B_Aufbau: B9; ash B_Rutschhemmung: R9
Gipsfaserplatten 2-lagig (BSK) | WUN-H2-E01-001 | CEILING | layer 0.036 m | 1166Dfl0000033086/01 | m² | Trockenbauarbeiten | 1 | 0.036 | 0 | 1 | Deckenfläche |  | 0 | 0 | NEW | 2.5 | AllplanAttributes - Bezeichnung: Gipsfaserplatten 2-lagig (BSK); RoomName: Schmutzwäsche, Müll
Gipsfaserplatten 2-lagig (BSK) | WUN-H2-E01-001 | CEILING | Installationshöhe 0.764 m | 1166Dfl0000033086/02 | m² | Trockenbauarbeiten | 2 | 0.764 | 0 | 1 | Bekleidung | Installationshöhe | 0 | 0 | NEW | 2.5 | AllplanAttributes - ash_lichte Raumhöhe: 2.500000; OKFF: 0; RoomName: Schmutzwäsche, Müll
Gipsfaserplatten 2-lagig (BSK) | WUN-H2-E01-001 | CEILING | A1 0.1 m | 1166Dfl0000033086/03 | m² | Trockenbauarbeiten | 3 | 0.1 | 0 | 1 | Bekleidung | A1 | 0 | 0 | NEW | 2.5 | AllplanAttributes - ash_lichte Raumhöhe: 2.500000; RoomName: Sprechzimmer; Pset_CoveringCommon - AcousticRating: -
Gipsfaserplatten 2-lagig (BSK) | WUN-H2-E01-001 | CEILING | D1 0.001 m | 1166Dfl0000033086/04 | m² | Maler- und Lackierarbeiten | 4 | 0.001 | 0 | 1 | Bekleidung | D1 | 0 | 0 | NEW | 2.5 | AllplanAttributes - ash_lichte Raumhöhe: 2.500000; OKFF: 0; RoomName: Schmutzwäsche, Müll
 | WUN-H2-E01-001 | CLADDING | 50 0.001 m | 1166Sfl0000667582/01 | m² | Maler- und Lackierarbeiten | 1 | 0.001 | 0 | 1 | Seitenfläche | 50 | 150 | 2500 | NEW
PVC | WUN-H2-E01-054 | FLOORING | Ku3 0.15 m | 1166Bfl0000034066/01 | m² | Bodenbelagsarbeiten | 1 | 0.15 | 0 | 1 | Bodenfläche | Ku3 | 0 | 0 | NEW | AllplanAttributes - Bezeichnung: PVC; Raumnr. Bauherr: 2.11_A2_02; ash B_Aufbau: B9; ash B_Rutschhemmung: R9
Gipsfaserplatten 2-lagig (BSK) | WUN-H2-E01-054 | CEILING | C/C 0.036 m | 1166Dfl0000034065/01 | m² | Trockenbauarbeiten | 1 | 0.036 | 0 | 1 | Deckenfläche | C/C | 0 | 0 | NEW | 3.364 | AllplanAttributes - Bezeichnung: Gipsfaserplatten 2-lagig (BSK); RoomName: SV
Gipsfaserplatten 2-lagig (BSK) | WUN-H2-E01-054 | CEILING | D4 0.001 m | 1166Dfl0000034065/02 | m² | Maler- und Lackierarbeiten | 2 | 0.001 | 0 | 1 | Deckenfläche | D4 | 0 | 0 | NEW
 | WUN-H2-E01-054 | CLADDING | 50 0.001 m | 1166Sfl0000667583/01 | m² | Maler- und Lackierarbeiten | 1 | 0.001 | 0 | 1 | Seitenfläche | 50 | 150 | 2500 | NEW
PVC | WUN-H2-E01-087 | FLOORING | Ku3 0.15 m | 1166Bfl0000034359/01 | m² | Bodenbelagsarbeiten | 1 | 0.15 | 0 | 1 | Bodenfläche | Ku3 | 0 | 0 | NEW | AllplanAttributes - Bezeichnung: PVC; Raumnr. Bauherr: 2.11_A2_02; ash B_Aufbau: B9; ash B_Rutschhemmung: R9
Gipsfaserplatten 2-lagig (BSK) | WUN-H2-E01-087 | CEILING | C/C 0.036 m | 1166Dfl0000034360/01 | m² | Trockenbauarbeiten | 1 | 0.036 | 0 | 1 | Deckenfläche | C/C | 0 | 0 | NEW | 3.364 | AllplanAttributes - Bezeichnung: Gipsfaserplatten 2-lagig (BSK); RoomName: SV
Gipsfaserplatten 2-lagig (BSK) | WUN-H2-E01-087 | CEILING | D4 0.001 m | 1166Dfl0000034360/02 | m² | Maler- und Lackierarbeiten | 2 | 0.001 | 0 | 1 | Deckenfläche | D4 | 0 | 0 | NEW
 | WUN-H2-E01-087 | CLADDING | 50 0.001 m | 1166Sfl0000667584/01 | m² | Maler- und Lackierarbeiten | 1 | 0.001 | 0 | 1 | Seitenfläche | 50 | 150 | 2500 | NEW
PVC | WUN-H2-E01-088 | FLOORING | Ku3 0.15 m | 1166Bfl0000034370/01 | m² | Bodenbelagsarbeiten | 1 | 0.15 | 0 | 1 | Bodenfläche | Ku3 | 0 | 0 | NEW | AllplanAttributes - Bezeichnung: PVC; Raumnr. Bauherr: 2.11_A2_02; ash B_Aufbau: B9; ash B_Rutschhemmung: R9
Gipsfaserplatten 2-lagig (BSK) | WUN-H2-E01-088 | CEILING | C/C 0.036 m | 1166Dfl0000034371/01 | m² | Trockenbauarbeiten | 1 | 0.036 | 0 | 1 | Deckenfläche | C/C | 0 | 0 | NEW | 3.364 | AllplanAttributes - Bezeichnung: Gipsfaserplatten 2-lagig (BSK); RoomName: SV
Gipsfaserplatten 2-lagig (BSK) | WUN-H2-E01-088 | CEILING | D4 0.001 m | 1166Dfl0000034371/02 | m² | Maler- und Lackierarbeiten | 2 | 0.001 | 0 | 1 | Deckenfläche | D4 | 0 | 0 | NEW
 | WUN-H2-E01-088 | CLADDING | 50 0.001 m | 1166Sfl0000667585/01 | m² | Maler- und Lackierarbeiten | 1 | 0.001 | 0 | 1 | Seitenfläche | 50 | 150 | 2500 | NEW
PVC | WUN-H2-E01-053 | FLOORING | Ku3 0.15 m | 1166Bfl0000034055/01 | m² | Bodenbelagsarbeiten | 1 | 0.15 | 0 | 1 | Bodenfläche | Ku3 | 0 | 0 | NEW | AllplanAttributes - Bezeichnung: PVC; Raumnr. Bauherr: 2.11_A2_02; ash B_Aufbau: B9; ash B_Rutschhemmung: R9
Gipsfaserplatten 2-lagig (BSK) | WUN-H2-E01-053 | CEILING | C/C 0.036 m | 1166Dfl0000034054/01 | m² | Trockenbauarbeiten | 1 | 0.036 | 0 | 1 | Deckenfläche | C/C | 0 | 0 | NEW | 3.364 | AllplanAttributes - Bezeichnung: Gipsfaserplatten 2-lagig (BSK); RoomName: SV
Gipsfaserplatten 2-lagig (BSK) | WUN-H2-E01-053 | CEILING | D4 0.001 m | 1166Dfl0000034054/02 | m² | Maler- und Lackierarbeiten | 2 | 0.001 | 0 | 1 | Deckenfläche | D4 | 0 | 0 | NEW
 | WUN-H2-E01-053 | CLADDING | 50 0.001 m | 1166Sfl0000667586/01 | m² | Maler- und Lackierarbeiten | 1 | 0.001 | 0 | 1 | Seitenfläche | 50 | 150 | 2500 | NEW
PVC | WUN-H2-E01-S01 | FLOORING | Ku3 0.15 m | 1166Bfl0000034583/01 | m² | Bodenbelagsarbeiten | 1 | 0.15 | 0 | 1 | Bodenfläche | Ku3 | 0 | 0 | NEW | AllplanAttributes - Bezeichnung: PVC; Raumnr. Bauherr: 2.11_A2_02; ash B_Aufbau: B9; ash B_Rutschhemmung: R9
Gipsfaserplatten 2-lagig (BSK) | WUN-H2-E01-S01 | CEILING | C/C 0.036 m | 1166Dfl0000034582/01 | m² | Trockenbauarbeiten | 1 | 0.036 | 0 | 1 | Deckenfläche | C/C | 0 | 0 | NEW | 3.364 | AllplanAttributes - Bezeichnung: Gipsfaserplatten 2-lagig (BSK); RoomName: SV
Gipsfaserplatten 2-lagig (BSK) | WUN-H2-E01-S01 | CEILING | D4 0.001 m | 1166Dfl0000034582/02 | m² | Maler- und Lackierarbeiten | 2 | 0.001 | 0 | 1 | Bekleidung | D4 | 0 | 0 | NEW | 3.15 | AllplanAttributes - ash_lichte Raumhöhe: 3.364000; RoomName: Hausanschluss
 | WUN-H2-E01-S01 | CLADDING | 50 0.001 m | 1166Sfl0000667587/01 | m² | Maler- und Lackierarbeiten | 1 | 0.001 | 0 | 1 | Seitenfläche | 50 | 150 | 2500 | NEW
PVC Bahnenware Uni | WUN-H2-E01-002 | FLOORING | Ku2 0.15 m | 1166Bfl0000033098/01 | m² | Bodenbelagsarbeiten | 1 | 0.15 | 0 | 1 | Bodenfläche | Ku2 | 0 | 0 | NEW | AllplanAttributes - Bezeichnung: PVC Bahnenware Uni; Raumnr. Bauherr: 2.11_A2_02; ash B_Aufbau: B9; ash B_Rutschhemmung: R9
Gipsfaserplatten 2-lagig (BSK) | WUN-H2-E01-002 | CEILING | layer 0.036 m | 1166Dfl0000033099/01 | m² | Trockenbauarbeiten | 1 | 0.036 | 0 | 1 | Deckenfläche |  | 0 | 0 | NEW | 2.5 | AllplanAttributes - Bezeichnung: Gipsfaserplatten 2-lagig (BSK); RoomName: Lager Versorgungsgüter
Gipsfaserplatten 2-lagig (BSK) | WUN-H2-E01-002 | CEILING | Installationshöhe 0.764 m | 1166Dfl0000033099/02 | m² | Trockenbauarbeiten | 2 | 0.764 | 0 | 1 | Bekleidung | Installationshöhe | 0 | 0 | NEW | 2.5 | AllplanAttributes - ash_lichte Raumhöhe: (7150-36+764+100)/1000-3.75; OKFF: 0; RoomName: Lager Versorgungsgüter
Rasterdecke | WUN-H2-E01-002 | CEILING | E3 0.1 m | 1166Dfl0000033099/03 | m² | Trockenbauarbeiten | 3 | 0.1 | 0 | 1 | Bekleidung | E3 | 0 | 0 | NEW | 2.5 | AllplanAttributes - Bezeichnung: Rasterdecke; ash_lichte Raumhöhe: (7150-36+764+100)/1000-3.75; OKFF: 0; RoomName: Lager Versorgungsgüter; Pset_CoveringCommon - AcousticRating: -
 | WUN-H2-E01-002 | CLADDING | 50 0.001 m | 1166Sfl0000667588/01 | m² | Maler- und Lackierarbeiten | 1 | 0.001 | 0 | 1 | Seitenfläche | 50 | 150 | 2500 | NEW
PVC Bahnenware Uni | WUN-H2-E01-075 | FLOORING | Ku2 0.15 m | 1166Bfl0000034022/01 | m² | Bodenbelagsarbeiten | 1 | 0.15 | 0 | 1 | Bodenfläche | Ku2 | 0 | 0 | NEW | AllplanAttributes - Bezeichnung: PVC Bahnenware Uni; Raumnr. Bauherr: 2.11_A2_02; ash B_Aufbau: B9; ash B_Rutschhemmung: R9
Gipsfaserplatten 2-lagig (BSK) | WUN-H2-E01-075 | CEILING | layer 0.036 m | 1166Dfl0000034021/01 | m² | Trockenbauarbeiten | 1 | 0.036 | 0 | 1 | Deckenfläche |  | 0 | 0 | NEW | 2.5 | AllplanAttributes - Bezeichnung: Gipsfaserplatten 2-lagig (BSK); RoomName: Geräte
Gipsfaserplatten 2-lagig (BSK) | WUN-H2-E01-075 | CEILING | Installationshöhe 0.764 m | 1166Dfl0000034021/02 | m² | Trockenbauarbeiten | 2 | 0.764 | 0 | 1 | Bekleidung | Installationshöhe | 0 | 0 | NEW | 2.5 | AllplanAttributes - ash_lichte Raumhöhe: (7150-36+764+100)/1000-3.75; OKFF: 0; RoomName: Geräte
Rasterdecke | WUN-H2-E01-075 | CEILING | E3 0.1 m | 1166Dfl0000034021/03 | m² | Trockenbauarbeiten | 3 | 0.1 | 0 | 1 | Bekleidung | E3 | 0 | 0 | NEW | 2.5 | AllplanAttributes - Bezeichnung: Rasterdecke; ash_lichte Raumhöhe: (7150-36+764+100)/1000-3.75; OKFF: 0; RoomName: Geräte; Pset_CoveringCommon - AcousticRating: -
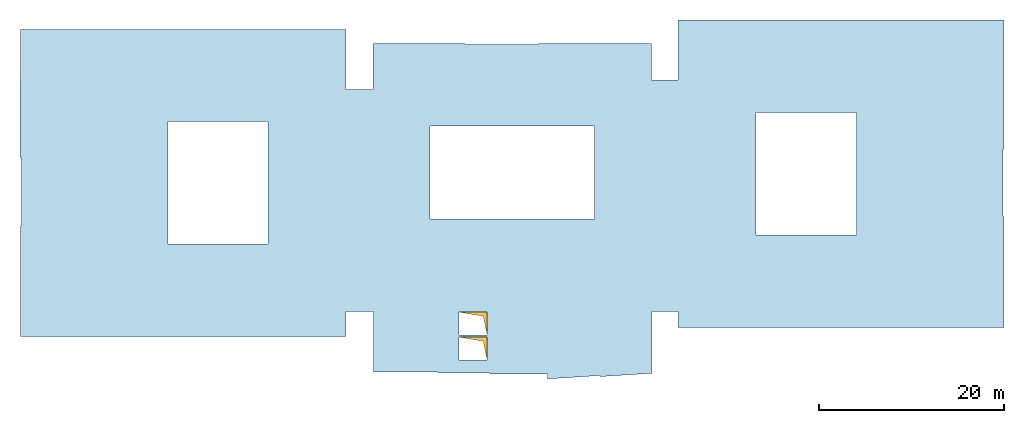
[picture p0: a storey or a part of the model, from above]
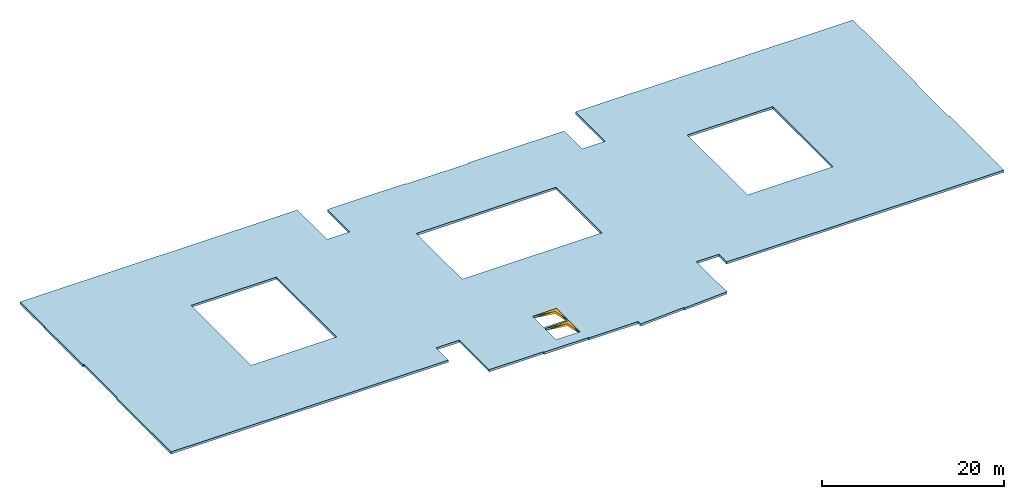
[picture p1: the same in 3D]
Properties of the parts of a building model (IFC4), part 16 of 80

# IfcCovering (3945)
Name | In | PredefinedType | Material | Allright_Bauteil_ID | Abrechnungsart | Gewerk | Schichtnummer | Schichtdicke (m) | Dicke (m) | Faktor | Objektname | AllplanAttributes, Material | Bezugshöhe | Deltahöhe | Status | D_lichte Raumhöhe [Zahl] (m)
 | WUN-H2-E01-075 | CLADDING | 50 0.001 m | 1166Sfl0000667589/01 | m² | Maler- und Lackierarbeiten | 1 | 0.001 | 0 | 1 | Seitenfläche | 50 | 150 | 2500 | NEW
PVC Bahnenware Uni | WUN-H2-E01-077 | FLOORING | Ku2 0.15 m | 1166Bfl0000034044/01 | m² | Bodenbelagsarbeiten | 1 | 0.15 | 0 | 1 | Bodenfläche | Ku2 | 0 | 0 | NEW | AllplanAttributes - Bezeichnung: PVC Bahnenware Uni; Raumnr. Bauherr: 2.11_A2_02; ash B_Aufbau: B9; ash B_Rutschhemmung: R9
Gipsfaserplatten 2-lagig (BSK) | WUN-H2-E01-077 | CEILING | layer 0.036 m | 1166Dfl0000034043/01 | m² | Trockenbauarbeiten | 1 | 0.036 | 0 | 1 | Deckenfläche |  | 0 | 0 | NEW | 2.5 | AllplanAttributes - Bezeichnung: Gipsfaserplatten 2-lagig (BSK); RoomName: AR unrein
Gipsfaserplatten 2-lagig (BSK) | WUN-H2-E01-077 | CEILING | Installationshöhe 0.764 m | 1166Dfl0000034043/02 | m² | Trockenbauarbeiten | 2 | 0.764 | 0 | 1 | Bekleidung | Installationshöhe | 0 | 0 | NEW | 2.5 | AllplanAttributes - ash_lichte Raumhöhe: (7150-36+764+100)/1000-3.75; OKFF: 0; RoomName: AR unrein
Rasterdecke | WUN-H2-E01-077 | CEILING | E3 0.1 m | 1166Dfl0000034043/03 | m² | Trockenbauarbeiten | 3 | 0.1 | 0 | 1 | Bekleidung | E3 | 0 | 0 | NEW | 2.5 | AllplanAttributes - Bezeichnung: Rasterdecke; ash_lichte Raumhöhe: (7150-36+764+100)/1000-3.75; OKFF: 0; RoomName: AR unrein; Pset_CoveringCommon - AcousticRating: -
 | WUN-H2-E01-077 | CLADDING | 50 0.001 m | 1166Sfl0000667590/01 | m² | Maler- und Lackierarbeiten | 1 | 0.001 | 0 | 1 | Seitenfläche | 50 | 150 | 2500 | NEW
PVC Bahnenware Uni | WUN-H2-E01-078 | FLOORING | Ku2 0.15 m | 1166Bfl0000034264/01 | m² | Bodenbelagsarbeiten | 1 | 0.15 | 0 | 1 | Bodenfläche | Ku2 | 0 | 0 | NEW | AllplanAttributes - Bezeichnung: PVC Bahnenware Uni; Raumnr. Bauherr: 2.11_A2_02; ash B_Aufbau: B9; ash B_Rutschhemmung: R9
Gipsfaserplatten 2-lagig (BSK) | WUN-H2-E01-078 | CEILING | layer 0.036 m | 1166Dfl0000034263/01 | m² | Trockenbauarbeiten | 1 | 0.036 | 0 | 1 | Deckenfläche |  | 0 | 0 | NEW | 2.5 | AllplanAttributes - Bezeichnung: Gipsfaserplatten 2-lagig (BSK); RoomName: Wäsche rein
Gipsfaserplatten 2-lagig (BSK) | WUN-H2-E01-078 | CEILING | Installationshöhe 0.764 m | 1166Dfl0000034263/02 | m² | Trockenbauarbeiten | 2 | 0.764 | 0 | 1 | Bekleidung | Installationshöhe | 0 | 0 | NEW | 2.5 | AllplanAttributes - ash_lichte Raumhöhe: (7150-36+764+100)/1000-3.75; OKFF: 0; RoomName: Wäsche rein
Rasterdecke | WUN-H2-E01-078 | CEILING | E3 0.1 m | 1166Dfl0000034263/03 | m² | Trockenbauarbeiten | 3 | 0.1 | 0 | 1 | Bekleidung | E3 | 0 | 0 | NEW | 2.5 | AllplanAttributes - Bezeichnung: Rasterdecke; ash_lichte Raumhöhe: (7150-36+764+100)/1000-3.75; OKFF: 0; RoomName: Wäsche rein; Pset_CoveringCommon - AcousticRating: -
 | WUN-H2-E01-078 | CLADDING | 50 0.001 m | 1166Sfl0000667591/01 | m² | Maler- und Lackierarbeiten | 1 | 0.001 | 0 | 1 | Seitenfläche | 50 | 150 | 2500 | NEW
PVC | WUN-H2-E01-081 | FLOORING | Ku3 0.15 m | 1166Bfl0000034297/01 | m² | Bodenbelagsarbeiten | 1 | 0.15 | 0 | 1 | Bodenfläche | Ku3 | 0 | 0 | NEW | AllplanAttributes - Bezeichnung: PVC; Raumnr. Bauherr: 2.11_A2_02; ash B_Aufbau: B9; ash B_Rutschhemmung: R9
Gipsfaserplatten 2-lagig (BSK) | WUN-H2-E01-081 | CEILING | layer 0.036 m | 1166Dfl0000034296/01 | m² | Trockenbauarbeiten | 1 | 0.036 | 0 | 1 | Deckenfläche |  | 0 | 0 | NEW | 2.5 | AllplanAttributes - Bezeichnung: Gipsfaserplatten 2-lagig (BSK); RoomName: EDV
Gipsfaserplatten 2-lagig (BSK) | WUN-H2-E01-081 | CEILING | Installationshöhe 0.764 m | 1166Dfl0000034296/02 | m² | Trockenbauarbeiten | 2 | 0.764 | 0 | 1 | Bekleidung | Installationshöhe | 0 | 0 | NEW | 2.5 | AllplanAttributes - ash_lichte Raumhöhe: (7150-36+764+100)/1000-3.75; RoomName: EDV; Pset_CoveringCommon - AcousticRating: -
Rasterdecke | WUN-H2-E01-081 | CEILING | E3 0.1 m | 1166Dfl0000034296/03 | m² | Trockenbauarbeiten | 3 | 0.1 | 0 | 1 | Bekleidung | E3 | 0 | 0 | NEW | 2.5 | AllplanAttributes - Bezeichnung: Rasterdecke; ash_lichte Raumhöhe: (7150-36+764+100)/1000-3.75; OKFF: 0; RoomName: Wäsche rein; Pset_CoveringCommon - AcousticRating: -
 | WUN-H2-E01-081 | CLADDING | 50 0.001 m | 1166Sfl0000667592/01 | m² | Maler- und Lackierarbeiten | 1 | 0.001 | 0 | 1 | Seitenfläche | 50 | 150 | 2500 | NEW
PVC Bahnenware Uni | WUN-H2-E01-089 | FLOORING | Ku2 0.15 m | 1166Bfl0000034381/01 | m² | Bodenbelagsarbeiten | 1 | 0.15 | 0 | 1 | Bodenfläche | Ku2 | 0 | 0 | NEW | AllplanAttributes - Bezeichnung: PVC Bahnenware Uni; Raumnr. Bauherr: 2.11_A2_02; ash B_Aufbau: B9; ash B_Rutschhemmung: R9
Gipsfaserplatten 2-lagig (BSK) | WUN-H2-E01-089 | CEILING | layer 0.036 m | 1166Dfl0000034382/01 | m² | Trockenbauarbeiten | 1 | 0.036 | 0 | 1 | Deckenfläche |  | 0 | 0 | NEW | 2.5 | AllplanAttributes - Bezeichnung: Gipsfaserplatten 2-lagig (BSK); RoomName: Lager Fixierbett
Gipsfaserplatten 2-lagig (BSK) | WUN-H2-E01-089 | CEILING | Installationshöhe 0.764 m | 1166Dfl0000034382/02 | m² | Trockenbauarbeiten | 2 | 0.764 | 0 | 1 | Bekleidung | Installationshöhe | 0 | 0 | NEW | 2.5 | AllplanAttributes - ash_lichte Raumhöhe: (7150-36+764+100)/1000-3.75; OKFF: 0; RoomName: Lager Fixierbett
Rasterdecke | WUN-H2-E01-089 | CEILING | E3 0.1 m | 1166Dfl0000034382/03 | m² | Trockenbauarbeiten | 3 | 0.1 | 0 | 1 | Bekleidung | E3 | 0 | 0 | NEW | 2.5 | AllplanAttributes - Bezeichnung: Rasterdecke; ash_lichte Raumhöhe: (7150-36+764+100)/1000-3.75; OKFF: 0; RoomName: Lager Fixierbett; Pset_CoveringCommon - AcousticRating: -
 | WUN-H2-E01-089 | CLADDING | 50 0.001 m | 1166Sfl0000667593/01 | m² | Maler- und Lackierarbeiten | 1 | 0.001 | 0 | 1 | Seitenfläche | 50 | 150 | 2500 | NEW
Fliesen | WUN-H2-E01-052 | FLOORING | Fl1 0.15 m | 1166Bfl0000034704/01 | m² | Bodenbelagsarbeiten | 1 | 0.15 | 0 | 1 | Bodenfläche | Fl1 | 0 | 0 | NEW | AllplanAttributes - Bezeichnung: Fliesen; Raumnr. Bauherr: 2.11_A2_02; ash B_Aufbau: B10; ash B_Rutschhemmung: R10
Gipsfaserplatten 2-lagig (BSK) | WUN-H2-E01-052 | CEILING | layer 0.036 m | 1166Dfl0000034703/01 | m² | Trockenbauarbeiten | 1 | 0.036 | 0 | 1 | Deckenfläche |  | 0 | 0 | NEW | 2.5 | AllplanAttributes - Bezeichnung: Gipsfaserplatten 2-lagig (BSK); RoomName: Vorraum WC
Gipsfaserplatten 2-lagig (BSK) | WUN-H2-E01-052 | CEILING | Installationshöhe 0.764 m | 1166Dfl0000034703/02 | m² | Trockenbauarbeiten | 2 | 0.764 | 0 | 1 | Bekleidung | Installationshöhe | 0 | 0 | NEW | 2.5 | AllplanAttributes - ash_lichte Raumhöhe: 2.500000; OKFF: 0; RoomName: Vorraum WC
Gipskarton, imprägniert | WUN-H2-E01-052 | CEILING | B 0.1 m | 1166Dfl0000034703/03 | m² | Trockenbauarbeiten | 3 | 0.1 | 0 | 1 | Bekleidung | B | 0 | 0 | NEW | 2.5 | AllplanAttributes - Bezeichnung: Gipskarton, imprägniert; ash_lichte Raumhöhe: 2.500000; OKFF: 0; RoomName: Vorraum WC; Pset_CoveringCommon - AcousticRating: -
Gipsfaserplatten 2-lagig (BSK) | WUN-H2-E01-052 | CEILING | D1 0.001 m | 1166Dfl0000034703/04 | m² | Maler- und Lackierarbeiten | 4 | 0.001 | 0 | 1 | Bekleidung | D1 | 0 | 0 | NEW | 2.5 | AllplanAttributes - ash_lichte Raumhöhe: 2.500000; OKFF: 0; RoomName: Vorraum WC
 | WUN-H2-E01-052 | CLADDING | 50 0.001 m | 1166Sfl0000667736/01 | m² | Maler- und Lackierarbeiten | 1 | 0.001 | 0 | 1 | Seitenfläche | 50 | 150 | 2500 | NEW
Fliesen | WUN-H2-E01-064b | FLOORING | Fl1 0.15 m | 1166Bfl0000034194/01 | m² | Bodenbelagsarbeiten | 1 | 0.15 | 0 | 1 | Bodenfläche | Fl1 | 0 | 0 | NEW | AllplanAttributes - Bezeichnung: Fliesen; Raumnr. Bauherr: 2.11_A2_02; ash B_Aufbau: B10; ash B_Rutschhemmung: R10
Gipsfaserplatten 2-lagig (BSK) | WUN-H2-E01-064b | CEILING | layer 0.036 m | 1166Dfl0000034195/01 | m² | Trockenbauarbeiten | 1 | 0.036 | 0 | 1 | Deckenfläche |  | 0 | 0 | NEW | 2.5 | AllplanAttributes - Bezeichnung: Gipsfaserplatten 2-lagig (BSK); RoomName: WC Krisenzimmer
Gipsfaserplatten 2-lagig (BSK) | WUN-H2-E01-064b | CEILING | Installationshöhe 0.764 m | 1166Dfl0000034195/02 | m² | Trockenbauarbeiten | 2 | 0.764 | 0 | 1 | Bekleidung | Installationshöhe | 0 | 0 | NEW | 2.5 | AllplanAttributes - ash_lichte Raumhöhe: 2.500000; OKFF: 0; RoomName: WC Krisenzimmer
Gipskarton, imprägniert | WUN-H2-E01-064b | CEILING | B 0.1 m | 1166Dfl0000034195/03 | m² | Trockenbauarbeiten | 3 | 0.1 | 0 | 1 | Bekleidung | B | 0 | 0 | NEW | 2.5 | AllplanAttributes - Bezeichnung: Gipskarton, imprägniert; ash_lichte Raumhöhe: 2.500000; OKFF: 0; RoomName: WC Krisenzimmer; Pset_CoveringCommon - AcousticRating: -
Gipsfaserplatten 2-lagig (BSK) | WUN-H2-E01-064b | CEILING | D1 0.001 m | 1166Dfl0000034195/04 | m² | Maler- und Lackierarbeiten | 4 | 0.001 | 0 | 1 | Bekleidung | D1 | 0 | 0 | NEW | 2.5 | AllplanAttributes - ash_lichte Raumhöhe: 2.500000; OKFF: 0; RoomName: WC Krisenzimmer
a-sh Wandbelag | WUN-H2-E01-064b | CLADDING | 64 0.01 m | 1166Sfl0000668525/01 | m² | Maler- und Lackierarbeiten | 1 | 0.01 | 0 | 1 | Seitenfläche | 64 | 100 | 3000 | NEW | AllplanAttributes - Bezeichnung: a-sh Wandbelag; Attributset-Objekt: Covering
PVC Bahnenware Uni | WUN-H2-E01-051 | FLOORING | Ku2 0.15 m | 1166Bfl0000033820/01 | m² | Bodenbelagsarbeiten | 1 | 0.15 | 0 | 1 | Bodenfläche | Ku2 | 0 | 0 | NEW | AllplanAttributes - Bezeichnung: PVC Bahnenware Uni; Raumnr. Bauherr: 2.11_A2_02; ash B_Aufbau: B9; ash B_Rutschhemmung: R9
Gipsfaserplatten 2-lagig (BSK) | WUN-H2-E01-051 | CEILING | layer 0.036 m | 1166Dfl0000042730/01 | m² | Trockenbauarbeiten | 1 | 0.036 | 0 | 1 | Deckenfläche |  | 0 | 0 | NEW | 2.5 | AllplanAttributes - Bezeichnung: Gipsfaserplatten 2-lagig (BSK); RoomName: Hauswirtschaftsraum
Gipsfaserplatten 2-lagig (BSK) | WUN-H2-E01-051 | CEILING | Installationshöhe 0.764 m | 1166Dfl0000042730/02 | m² | Trockenbauarbeiten | 2 | 0.764 | 0 | 1 | Bekleidung | Installationshöhe | 0 | 0 | NEW | 2.5 | AllplanAttributes - ash_lichte Raumhöhe: 2.500000; OKFF: 0; RoomName: Hauswirtschaftsraum
Gipsfaserplatten 2-lagig (BSK) | WUN-H2-E01-051 | CEILING | A1 0.1 m | 1166Dfl0000042730/03 | m² | Trockenbauarbeiten | 3 | 0.1 | 0 | 1 | Bekleidung | A1 | 0 | 0 | NEW | 2.5 | AllplanAttributes - ash_lichte Raumhöhe: 2.500000; OKFF: 0; RoomName: Hauswirtschaftsraum; Pset_CoveringCommon - AcousticRating: -
Gipsfaserplatten 2-lagig (BSK) | WUN-H2-E01-051 | CEILING | D1 0.001 m | 1166Dfl0000042730/04 | m² | Maler- und Lackierarbeiten | 4 | 0.001 | 0 | 1 | Bekleidung | D1 | 0 | 0 | NEW | 2.5 | AllplanAttributes - ash_lichte Raumhöhe: 2.500000; OKFF: 0; RoomName: Hauswirtschaftsraum
Gipsfaserplatten 2-lagig (BSK) | WUN-H2-E01-051 | CEILING | layer 0.036 m | 1166Dfl0000231665/01 | m² | Trockenbauarbeiten | 1 | 0.036 | 0 | 1 | Deckenfläche |  | 0 | 0 | NEW | 2.5 | AllplanAttributes - Bezeichnung: Gipsfaserplatten 2-lagig (BSK); RoomName: Hauswirtschaftsraum
Gipsfaserplatten 2-lagig (BSK) | WUN-H2-E01-051 | CEILING | Installationshöhe 0.764 m | 1166Dfl0000231665/02 | m² | Trockenbauarbeiten | 2 | 0.764 | 0 | 1 | Bekleidung | Installationshöhe | 0 | 0 | NEW | 2.5 | AllplanAttributes - ash_lichte Raumhöhe: 2.500000; OKFF: 0; RoomName: Hauswirtschaftsraum
Gipsfaserplatten 2-lagig (BSK) | WUN-H2-E01-051 | CEILING | A1 0.1 m | 1166Dfl0000231665/03 | m² | Trockenbauarbeiten | 3 | 0.1 | 0 | 1 | Bekleidung | A1 | 0 | 0 | NEW | 2.5 | AllplanAttributes - ash_lichte Raumhöhe: 2.500000; OKFF: 0; RoomName: Hauswirtschaftsraum; Pset_CoveringCommon - AcousticRating: -
Gipsfaserplatten 2-lagig (BSK) | WUN-H2-E01-051 | CEILING | D1 0.001 m | 1166Dfl0000231665/04 | m² | Maler- und Lackierarbeiten | 4 | 0.001 | 0 | 1 | Bekleidung | D1 | 0 | 0 | NEW | 2.5 | AllplanAttributes - ash_lichte Raumhöhe: 2.500000; OKFF: 0; RoomName: Hauswirtschaftsraum
 | WUN-H2-E01-051 | CLADDING | 50 0.001 m | 1166Sfl0000668526/01 | m² | Maler- und Lackierarbeiten | 1 | 0.001 | 0 | 1 | Seitenfläche | 50 | 150 | 3150 | NEW
Gipsfaserplatten 2-lagig (BSK) | WUN-H2-E01-073 | CEILING | layer 0.036 m | 1166Dfl0000034165/01 | m² | Trockenbauarbeiten | 1 | 0.036 | 0 | 1 | Deckenfläche |  | 0 | 0 | NEW | 2.5 | AllplanAttributes - Bezeichnung: Gipsfaserplatten 2-lagig (BSK); RoomName: DR Therapeut
Gipsfaserplatten 2-lagig (BSK) | WUN-H2-E01-073 | CEILING | Installationshöhe 0.714 m | 1166Dfl0000034165/02 | m² | Trockenbauarbeiten | 2 | 0.714 | 0 | 1 | Bekleidung | Installationshöhe | 0 | 0 | NEW | 2.5 | AllplanAttributes - ash_lichte Raumhöhe: 2.500000; OKFF: 0; RoomName: DR Therapeut
Gipsfaserplatten 2-lagig (BSK) | WUN-H2-E01-073 | CEILING | A1 0.15 m | 1166Dfl0000034165/03 | m² | Trockenbauarbeiten | 3 | 0.15 | 0 | 1 | Bekleidung | A1 | 0 | 0 | NEW | 2.5 | AllplanAttributes - ash_lichte Raumhöhe: 2.500000; OKFF: 0; RoomName: DR Therapeut; Pset_CoveringCommon - AcousticRating: -
Gipsfaserplatten 2-lagig (BSK) | WUN-H2-E01-073 | CEILING | D1 0.001 m | 1166Dfl0000034165/04 | m² | Maler- und Lackierarbeiten | 4 | 0.001 | 0 | 1 | Bekleidung | D1 | 0 | 0 | NEW | 2.5 | AllplanAttributes - ash_lichte Raumhöhe: 2.500000; OKFF: 0; RoomName: DR Therapeut
Gipsfaserplatten 2-lagig (BSK) | WUN-H2-E01-073 | CEILING | layer 0.036 m | 1166Dfl0000454015/01 | m² | Trockenbauarbeiten | 1 | 0.036 | 0 | 1 | Deckenfläche |  | 0 | 0 | NEW | 2.5 | AllplanAttributes - Bezeichnung: Gipsfaserplatten 2-lagig (BSK); RoomName: Freizeit / Club
Gipsfaserplatten 2-lagig (BSK) | WUN-H2-E01-073 | CEILING | Installationshöhe 0.714 m | 1166Dfl0000454015/02 | m² | Trockenbauarbeiten | 2 | 0.714 | 0 | 1 | Bekleidung | Installationshöhe | 0 | 0 | NEW | 2.5 | AllplanAttributes - ash_lichte Raumhöhe: 2.500000; OKFF: 0; RoomName: Freizeit / Club
Gipsfaserplatten 2-lagig (BSK) | WUN-H2-E01-073 | CEILING | Aa 0.15 m | 1166Dfl0000454015/03 | m² | Trockenbauarbeiten | 3 | 0.15 | 0 | 1 | Bekleidung | Aa | 0 | 0 | NEW | 2.5 | AllplanAttributes - ash_lichte Raumhöhe: 2.500000; OKFF: 0; RoomName: Freizeit / Club; Pset_CoveringCommon - AcousticRating: -
Gipsfaserplatten 2-lagig (BSK) | WUN-H2-E01-073 | CEILING | D1 0.001 m | 1166Dfl0000454015/04 | m² | Maler- und Lackierarbeiten | 4 | 0.001 | 0 | 1 | Bekleidung | D1 | 0 | 0 | NEW | 2.5 | AllplanAttributes - ash_lichte Raumhöhe: 2.500000; OKFF: 0; RoomName: Freizeit / Club
PVC Bahnenware Holzoptik | WUN-H2-E01-073 | FLOORING | Ku1 0.15 m | 1166Bfl0000034154/01 | m² | Bodenbelagsarbeiten | 1 | 0.15 | 0 | 1 | Bodenfläche | Ku1 | 0 | 0 | NEW | AllplanAttributes - Bezeichnung: PVC Bahnenware Holzoptik; Raumnr. Bauherr: 2.11_A2_02; ash B_Aufbau: B9; ash B_Rutschhemmung: R9
Gipsfaserplatten 2-lagig (BSK) | WUN-H2-E01-073 | CEILING | layer 0.036 m | 1166Dfl0000034155/01 | m² | Trockenbauarbeiten | 1 | 0.036 | 0 | 1 | Deckenfläche |  | 0 | 0 | NEW | 3.1 | AllplanAttributes - Bezeichnung: Gipsfaserplatten 2-lagig (BSK); RoomName: Sprechzimmer
Gipsfaserplatten 2-lagig (BSK) | WUN-H2-E01-073 | CEILING | Installationshöhe 0.164 m | 1166Dfl0000034155/02 | m² | Trockenbauarbeiten | 2 | 0.164 | 0 | 1 | Bekleidung | Installationshöhe | 0 | 0 | NEW | 3.1 | AllplanAttributes - ash_lichte Raumhöhe: 3.100000; RoomName: Sprechzimmer; Pset_CoveringCommon - AcousticRating: -
Gipsfaserplatten 2-lagig (BSK) | WUN-H2-E01-073 | CEILING | A1 0.1 m | 1166Dfl0000034155/03 | m² | Trockenbauarbeiten | 3 | 0.1 | 0 | 1 | Bekleidung | A1 | 0 | 0 | NEW | 3.1 | AllplanAttributes - ash_lichte Raumhöhe: 3.100000; RoomName: Sprechzimmer; Pset_CoveringCommon - AcousticRating: -
Gipsfaserplatten 2-lagig (BSK) | WUN-H2-E01-073 | CEILING | D1 0.001 m | 1166Dfl0000034155/04 | m² | Maler- und Lackierarbeiten | 4 | 0.001 | 0 | 1 | Bekleidung | D1 | 0 | 0 | NEW | 3.1 | AllplanAttributes - ash_lichte Raumhöhe: 3.100000; RoomName: Sprechzimmer
 | WUN-H2-E01-073 | CLADDING | 49 0.001 m | 1166Sfl0000666662/01 | m² | Maler- und Lackierarbeiten | 1 | 0.001 | 0 | 1 | Seitenfläche | 49 | 150 | 3150 | NEW
Gipsfaserplatten 2-lagig (BSK) | WUN-H2-E01-073 | CEILING | layer 0.036 m | 1166Dfl0000034152/01 | m² | Trockenbauarbeiten | 1 | 0.036 | 0 | 1 | Deckenfläche |  | 0 | 0 | NEW | 2.5 | AllplanAttributes - Bezeichnung: Gipsfaserplatten 2-lagig (BSK); RoomName: Aufenthalt / Besucher
Gipsfaserplatten 2-lagig (BSK) | WUN-H2-E01-073 | CEILING | Installationshöhe 0.714 m | 1166Dfl0000034152/02 | m² | Trockenbauarbeiten | 2 | 0.714 | 0 | 1 | Bekleidung | Installationshöhe | 0 | 0 | NEW | 2.5 | AllplanAttributes - ash_lichte Raumhöhe: 2.500000; OKFF: 0; RoomName: Aufenthalt / Besucher
Gipsfaserplatten 2-lagig (BSK) | WUN-H2-E01-073 | CEILING | A1 0.15 m | 1166Dfl0000034152/03 | m² | Trockenbauarbeiten | 3 | 0.15 | 0 | 1 | Bekleidung | A1 | 0 | 0 | NEW | 2.5 | AllplanAttributes - ash_lichte Raumhöhe: 2.500000; OKFF: 0; RoomName: Aufenthalt / Besucher; Pset_CoveringCommon - AcousticRating: -
Gipsfaserplatten 2-lagig (BSK) | WUN-H2-E01-073 | CEILING | D1 0.001 m | 1166Dfl0000034152/04 | m² | Maler- und Lackierarbeiten | 4 | 0.001 | 0 | 1 | Bekleidung | D1 | 0 | 0 | NEW | 2.5 | AllplanAttributes - ash_lichte Raumhöhe: 2.500000; OKFF: 0; RoomName: Aufenthalt / Besucher
Gipsfaserplatten 2-lagig (BSK) | WUN-H2-E01-073 | CEILING | layer 0.036 m | 1166Dfl0000454469/01 | m² | Trockenbauarbeiten | 1 | 0.036 | 0 | 1 | Deckenfläche |  | 0 | 0 | NEW | 2.5 | AllplanAttributes - Bezeichnung: Gipsfaserplatten 2-lagig (BSK); RoomName: Freizeit / Club
Gipsfaserplatten 2-lagig (BSK) | WUN-H2-E01-073 | CEILING | Installationshöhe 0.714 m | 1166Dfl0000454469/02 | m² | Trockenbauarbeiten | 2 | 0.714 | 0 | 1 | Bekleidung | Installationshöhe | 0 | 0 | NEW | 2.5 | AllplanAttributes - ash_lichte Raumhöhe: 2.500000; OKFF: 0; RoomName: Freizeit / Club
Gipsfaserplatten 2-lagig (BSK) | WUN-H2-E01-073 | CEILING | Aa 0.15 m | 1166Dfl0000454469/03 | m² | Trockenbauarbeiten | 3 | 0.15 | 0 | 1 | Bekleidung | Aa | 0 | 0 | NEW | 2.5 | AllplanAttributes - ash_lichte Raumhöhe: 2.500000; OKFF: 0; RoomName: Freizeit / Club; Pset_CoveringCommon - AcousticRating: -
Gipsfaserplatten 2-lagig (BSK) | WUN-H2-E01-073 | CEILING | D1 0.001 m | 1166Dfl0000454469/04 | m² | Maler- und Lackierarbeiten | 4 | 0.001 | 0 | 1 | Bekleidung | D1 | 0 | 0 | NEW | 2.5 | AllplanAttributes - ash_lichte Raumhöhe: 2.500000; OKFF: 0; RoomName: Freizeit / Club
PVC Bahnenware Holzoptik | WUN-H2-E01-073 | FLOORING | Ku1 0.15 m | 1166Bfl0000034141/01 | m² | Bodenbelagsarbeiten | 1 | 0.15 | 0 | 1 | Bodenfläche | Ku1 | 0 | 0 | NEW | AllplanAttributes - Bezeichnung: PVC Bahnenware Holzoptik; Raumnr. Bauherr: 2.11_A2_02; ash B_Aufbau: B9; ash B_Rutschhemmung: R9
Gipsfaserplatten 2-lagig (BSK) | WUN-H2-E01-073 | CEILING | layer 0.036 m | 1166Dfl0000034142/01 | m² | Trockenbauarbeiten | 1 | 0.036 | 0 | 1 | Deckenfläche |  | 0 | 0 | NEW | 3.1 | AllplanAttributes - Bezeichnung: Gipsfaserplatten 2-lagig (BSK); RoomName: Sprechzimmer
Gipsfaserplatten 2-lagig (BSK) | WUN-H2-E01-073 | CEILING | Installationshöhe 0.164 m | 1166Dfl0000034142/02 | m² | Trockenbauarbeiten | 2 | 0.164 | 0 | 1 | Bekleidung | Installationshöhe | 0 | 0 | NEW | 3.1 | AllplanAttributes - ash_lichte Raumhöhe: 3.100000; RoomName: Sprechzimmer; Pset_CoveringCommon - AcousticRating: -
Gipsfaserplatten 2-lagig (BSK) | WUN-H2-E01-073 | CEILING | A1 0.1 m | 1166Dfl0000034142/03 | m² | Trockenbauarbeiten | 3 | 0.1 | 0 | 1 | Bekleidung | A1 | 0 | 0 | NEW | 3.1 | AllplanAttributes - ash_lichte Raumhöhe: 3.100000; RoomName: Sprechzimmer; Pset_CoveringCommon - AcousticRating: -
Gipsfaserplatten 2-lagig (BSK) | WUN-H2-E01-073 | CEILING | D1 0.001 m | 1166Dfl0000034142/04 | m² | Maler- und Lackierarbeiten | 4 | 0.001 | 0 | 1 | Bekleidung | D1 | 0 | 0 | NEW | 3.1 | AllplanAttributes - ash_lichte Raumhöhe: 3.100000; RoomName: Sprechzimmer
 | WUN-H2-E01-073 | CLADDING | 49 0.001 m | 1166Sfl0000666661/01 | m² | Maler- und Lackierarbeiten | 1 | 0.001 | 0 | 1 | Seitenfläche | 49 | 150 | 3150 | NEW
Gipsfaserplatten 2-lagig (BSK) | WUN-H2-E01-073 | CEILING | layer 0.036 m | 1166Dfl0000453108/01 | m² | Trockenbauarbeiten | 1 | 0.036 | 0 | 1 | Deckenfläche |  | 0 | 0 | NEW | 2.5 | AllplanAttributes - Bezeichnung: Gipsfaserplatten 2-lagig (BSK); RoomName: Freizeit / Club
Gipsfaserplatten 2-lagig (BSK) | WUN-H2-E01-073 | CEILING | Installationshöhe 0.714 m | 1166Dfl0000453108/02 | m² | Trockenbauarbeiten | 2 | 0.714 | 0 | 1 | Bekleidung | Installationshöhe | 0 | 0 | NEW | 2.5 | AllplanAttributes - ash_lichte Raumhöhe: 2.500000; OKFF: 0; RoomName: Freizeit / Club
Gipsfaserplatten 2-lagig (BSK) | WUN-H2-E01-073 | CEILING | Aa 0.15 m | 1166Dfl0000453108/03 | m² | Trockenbauarbeiten | 3 | 0.15 | 0 | 1 | Bekleidung | Aa | 0 | 0 | NEW | 2.5 | AllplanAttributes - ash_lichte Raumhöhe: 2.500000; OKFF: 0; RoomName: Freizeit / Club; Pset_CoveringCommon - AcousticRating: -
Gipsfaserplatten 2-lagig (BSK) | WUN-H2-E01-073 | CEILING | D1 0.001 m | 1166Dfl0000453108/04 | m² | Maler- und Lackierarbeiten | 4 | 0.001 | 0 | 1 | Bekleidung | D1 | 0 | 0 | NEW | 2.5 | AllplanAttributes - ash_lichte Raumhöhe: 2.500000; OKFF: 0; RoomName: Freizeit / Club
Gipsfaserplatten 2-lagig (BSK) | WUN-H2-E01-073 | CEILING | layer 0.036 m | 1166Dfl0000033120/01 | m² | Trockenbauarbeiten | 1 | 0.036 | 0 | 1 | Deckenfläche |  | 0 | 0 | NEW | 2.5 | AllplanAttributes - Bezeichnung: Gipsfaserplatten 2-lagig (BSK); RoomName: Aufenthalt / Besucher
Gipsfaserplatten 2-lagig (BSK) | WUN-H2-E01-073 | CEILING | Installationshöhe 0.714 m | 1166Dfl0000033120/02 | m² | Trockenbauarbeiten | 2 | 0.714 | 0 | 1 | Bekleidung | Installationshöhe | 0 | 0 | NEW | 2.5 | AllplanAttributes - ash_lichte Raumhöhe: 2.500000; OKFF: 0; RoomName: Aufenthalt / Besucher
Gipsfaserplatten 2-lagig (BSK) | WUN-H2-E01-073 | CEILING | A1 0.15 m | 1166Dfl0000033120/03 | m² | Trockenbauarbeiten | 3 | 0.15 | 0 | 1 | Bekleidung | A1 | 0 | 0 | NEW | 2.5 | AllplanAttributes - ash_lichte Raumhöhe: 2.500000; OKFF: 0; RoomName: Aufenthalt / Besucher; Pset_CoveringCommon - AcousticRating: -
Gipsfaserplatten 2-lagig (BSK) | WUN-H2-E01-073 | CEILING | D1 0.001 m | 1166Dfl0000033120/04 | m² | Maler- und Lackierarbeiten | 4 | 0.001 | 0 | 1 | Bekleidung | D1 | 0 | 0 | NEW | 2.5 | AllplanAttributes - ash_lichte Raumhöhe: 2.500000; OKFF: 0; RoomName: Aufenthalt / Besucher
PVC Bahnenware Holzoptik | WUN-H2-E01-073 | FLOORING | Ku1 0.15 m | 1166Bfl0000033109/01 | m² | Bodenbelagsarbeiten | 1 | 0.15 | 0 | 1 | Bodenfläche | Ku1 | 0 | 0 | NEW | AllplanAttributes - Bezeichnung: PVC Bahnenware Holzoptik; Raumnr. Bauherr: 2.11_A2_02; ash B_Aufbau: B9; ash B_Rutschhemmung: R9
Gipsfaserplatten 2-lagig (BSK) | WUN-H2-E01-073 | CEILING | layer 0.036 m | 1166Dfl0000033110/01 | m² | Trockenbauarbeiten | 1 | 0.036 | 0 | 1 | Deckenfläche |  | 0 | 0 | NEW | 3.1 | AllplanAttributes - Bezeichnung: Gipsfaserplatten 2-lagig (BSK); RoomName: Sprechzimmer
Gipsfaserplatten 2-lagig (BSK) | WUN-H2-E01-073 | CEILING | Installationshöhe 0.164 m | 1166Dfl0000033110/02 | m² | Trockenbauarbeiten | 2 | 0.164 | 0 | 1 | Bekleidung | Installationshöhe | 0 | 0 | NEW | 3.1 | AllplanAttributes - ash_lichte Raumhöhe: 3.100000; RoomName: Sprechzimmer; Pset_CoveringCommon - AcousticRating: -
Gipsfaserplatten 2-lagig (BSK) | WUN-H2-E01-073 | CEILING | A1 0.1 m | 1166Dfl0000033110/03 | m² | Trockenbauarbeiten | 3 | 0.1 | 0 | 1 | Bekleidung | A1 | 0 | 0 | NEW | 3.1 | AllplanAttributes - ash_lichte Raumhöhe: 3.100000; RoomName: Sprechzimmer; Pset_CoveringCommon - AcousticRating: -
Gipsfaserplatten 2-lagig (BSK) | WUN-H2-E01-073 | CEILING | D1 0.001 m | 1166Dfl0000033110/04 | m² | Maler- und Lackierarbeiten | 4 | 0.001 | 0 | 1 | Bekleidung | D1 | 0 | 0 | NEW | 3.1 | AllplanAttributes - ash_lichte Raumhöhe: 3.100000; RoomName: Sprechzimmer
 | WUN-H2-E01-073 | CLADDING | 49 0.001 m | 1166Sfl0000666663/01 | m² | Maler- und Lackierarbeiten | 1 | 0.001 | 0 | 1 | Seitenfläche | 49 | 150 | 3150 | NEW
Gipsfaserplatten 2-lagig (BSK) | WUN-H2-E01-073 | CEILING | layer 0.036 m | 1166Dfl0000228170/01 | m² | Trockenbauarbeiten | 1 | 0.036 | 0 | 1 | Deckenfläche |  | 0 | 0 | NEW | 2.75 | AllplanAttributes - Bezeichnung: Gipsfaserplatten 2-lagig (BSK); RoomName: Backoffice
Gipsfaserplatten 2-lagig (BSK) | WUN-H2-E01-073 | CEILING | Installationshöhe 0.464 m | 1166Dfl0000228170/02 | m² | Trockenbauarbeiten | 2 | 0.464 | 0 | 1 | Bekleidung | Installationshöhe | 0 | 0 | NEW | 2.75 | AllplanAttributes - ash_lichte Raumhöhe: 2.750000; RoomName: Backoffice
Gipsfaserplatten 2-lagig (BSK) | WUN-H2-E01-073 | CEILING | Aa 0.15 m | 1166Dfl0000228170/03 | m² | Trockenbauarbeiten | 3 | 0.15 | 0 | 1 | Bekleidung | Aa | 0 | 0 | NEW | 2.75 | Pset_CoveringCommon - FireRating: -; AcousticRating: -; AllplanAttributes - ash_lichte Raumhöhe: 2.750000; RoomName: Backoffice
Gipsfaserplatten 2-lagig (BSK) | WUN-H2-E01-073 | CEILING | D1 0.001 m | 1166Dfl0000228170/04 | m² | Maler- und Lackierarbeiten | 4 | 0.001 | 0 | 1 | Bekleidung | D1 | 0 | 0 | NEW | 2.75 | AllplanAttributes - ash_lichte Raumhöhe: 2.750000; RoomName: Backoffice
Gipsfaserplatten 2-lagig (BSK) | WUN-H2-E01-073 | CEILING | layer 0.036 m | 1166Dfl0000042130/01 | m² | Trockenbauarbeiten | 1 | 0.036 | 0 | 1 | Deckenfläche |  | 0 | 0 | NEW | 2.75 | AllplanAttributes - Bezeichnung: Gipsfaserplatten 2-lagig (BSK); RoomName: Backoffice
Gipsfaserplatten 2-lagig (BSK) | WUN-H2-E01-073 | CEILING | Installationshöhe 0.464 m | 1166Dfl0000042130/02 | m² | Trockenbauarbeiten | 2 | 0.464 | 0 | 1 | Bekleidung | Installationshöhe | 0 | 0 | NEW | 2.75 | AllplanAttributes - ash_lichte Raumhöhe: 2.750000; RoomName: Backoffice
Gipsfaserplatten 2-lagig (BSK) | WUN-H2-E01-073 | CEILING | A1 0.15 m | 1166Dfl0000042130/03 | m² | Trockenbauarbeiten | 3 | 0.15 | 0 | 1 | Bekleidung | A1 | 0 | 0 | NEW | 2.75 | AllplanAttributes - ash_lichte Raumhöhe: 2.750000; RoomName: Backoffice; Pset_CoveringCommon - AcousticRating: -
Gipsfaserplatten 2-lagig (BSK) | WUN-H2-E01-073 | CEILING | D1 0.001 m | 1166Dfl0000042130/04 | m² | Maler- und Lackierarbeiten | 4 | 0.001 | 0 | 1 | Bekleidung | D1 | 0 | 0 | NEW | 2.75 | AllplanAttributes - ash_lichte Raumhöhe: 2.750000; RoomName: Backoffice
Gipsfaserplatten 2-lagig (BSK) | WUN-H2-E01-073 | CEILING | layer 0.036 m | 1166Dfl0000228750/01 | m² | Trockenbauarbeiten | 1 | 0.036 | 0 | 1 | Deckenfläche |  | 0 | 0 | NEW | 2.75 | AllplanAttributes - Bezeichnung: Gipsfaserplatten 2-lagig (BSK); RoomName: Backoffice
Gipsfaserplatten 2-lagig (BSK) | WUN-H2-E01-073 | CEILING | Installationshöhe 0.464 m | 1166Dfl0000228750/02 | m² | Trockenbauarbeiten | 2 | 0.464 | 0 | 1 | Bekleidung | Installationshöhe | 0 | 0 | NEW | 2.75 | AllplanAttributes - ash_lichte Raumhöhe: 2.750000; RoomName: Backoffice
Gipsfaserplatten 2-lagig (BSK) | WUN-H2-E01-073 | CEILING | Aa 0.15 m | 1166Dfl0000228750/03 | m² | Trockenbauarbeiten | 3 | 0.15 | 0 | 1 | Bekleidung | Aa | 0 | 0 | NEW | 2.75 | Pset_CoveringCommon - FireRating: -; AcousticRating: -; AllplanAttributes - ash_lichte Raumhöhe: 2.750000; RoomName: Backoffice
Gipsfaserplatten 2-lagig (BSK) | WUN-H2-E01-073 | CEILING | D1 0.001 m | 1166Dfl0000228750/04 | m² | Maler- und Lackierarbeiten | 4 | 0.001 | 0 | 1 | Bekleidung | D1 | 0 | 0 | NEW | 2.75 | AllplanAttributes - ash_lichte Raumhöhe: 2.750000; RoomName: Backoffice
PVC Bahnenware Holzoptik | WUN-H2-E01-073 | FLOORING | Ku1 0.15 m | 1166Bfl0000042122/01 | m² | Bodenbelagsarbeiten | 1 | 0.15 | 0 | 1 | Bodenfläche | Ku1 | 0 | 0 | NEW | AllplanAttributes - Bezeichnung: PVC Bahnenware Holzoptik; Raumnr. Bauherr: 2.11_A2_02; ash B_Aufbau: B9; ash B_Rutschhemmung: R9
 | WUN-H2-E01-073 | CLADDING | 49 0.001 m | 1166Sfl0000666652/01 | m² | Maler- und Lackierarbeiten | 1 | 0.001 | 0 | 1 | Seitenfläche | 49 | 150 | 3150 | NEW
Gipsfaserplatten 2-lagig (BSK) | WUN-H2-E01-073 | CEILING | layer 0.036 m | 1166Dfl0000437404/01 | m² | Trockenbauarbeiten | 1 | 0.036 | 0 | 1 | Deckenfläche |  | 0 | 0 | NEW | 2.5 | AllplanAttributes - Bezeichnung: Gipsfaserplatten 2-lagig (BSK); RoomName: Flur
Gipsfaserplatten 2-lagig (BSK) | WUN-H2-E01-073 | CEILING | Installationshöhe 0.714 m | 1166Dfl0000437404/02 | m² | Trockenbauarbeiten | 2 | 0.714 | 0 | 1 | Bekleidung | Installationshöhe | 0 | 0 | NEW | 2.5 | AllplanAttributes - ash_lichte Raumhöhe: 2.500000; RoomName: Flur
Gipsfaserplatten 2-lagig (BSK) | WUN-H2-E01-073 | CEILING | Aa 0.15 m | 1166Dfl0000437404/03 | m² | Trockenbauarbeiten | 3 | 0.15 | 0 | 1 | Bekleidung | Aa | 0 | 0 | NEW | 2.5 | AllplanAttributes - ash_lichte Raumhöhe: 2.500000; RoomName: Flur; Pset_CoveringCommon - AcousticRating: -
Gipsfaserplatten 2-lagig (BSK) | WUN-H2-E01-073 | CEILING | D1 0.001 m | 1166Dfl0000437404/04 | m² | Maler- und Lackierarbeiten | 4 | 0.001 | 0 | 1 | Bekleidung | D1 | 0 | 0 | NEW | 2.5 | AllplanAttributes - ash_lichte Raumhöhe: 2.500000; RoomName: Flur
PVC Bahnenware Holzoptik | WUN-H2-E01-073 | FLOORING | Ku1 0.15 m | 1166Bfl0000033225/01 | m² | Bodenbelagsarbeiten | 1 | 0.15 | 0 | 1 | Bodenfläche | Ku1 | 0 | 0 | NEW | AllplanAttributes - Bezeichnung: PVC Bahnenware Holzoptik; Raumnr. Bauherr: 2.11_A2_02; ash B_Aufbau: B9; ash B_Rutschhemmung: R9
Gipsfaserplatten 2-lagig (BSK) | WUN-H2-E01-073 | CEILING | layer 0.036 m | 1166Dfl0000437401/01 | m² | Trockenbauarbeiten | 1 | 0.036 | 0 | 1 | Deckenfläche |  | 0 | 0 | NEW | 2.5 | AllplanAttributes - Bezeichnung: Gipsfaserplatten 2-lagig (BSK); RoomName: Flur
Gipsfaserplatten 2-lagig (BSK) | WUN-H2-E01-073 | CEILING | Installationshöhe 0.714 m | 1166Dfl0000437401/02 | m² | Trockenbauarbeiten | 2 | 0.714 | 0 | 1 | Bekleidung | Installationshöhe | 0 | 0 | NEW | 2.5 | AllplanAttributes - ash_lichte Raumhöhe: 2.500000; RoomName: Flur
Gipsfaserplatten 2-lagig (BSK) | WUN-H2-E01-073 | CEILING | A1 0.15 m | 1166Dfl0000437401/03 | m² | Trockenbauarbeiten | 3 | 0.15 | 0 | 1 | Bekleidung | A1 | 0 | 0 | NEW | 2.5 | AllplanAttributes - ash_lichte Raumhöhe: 2.500000; RoomName: Flur; Pset_CoveringCommon - AcousticRating: -
Gipsfaserplatten 2-lagig (BSK) | WUN-H2-E01-073 | CEILING | D1 0.001 m | 1166Dfl0000437401/04 | m² | Maler- und Lackierarbeiten | 4 | 0.001 | 0 | 1 | Bekleidung | D1 | 0 | 0 | NEW | 2.5 | AllplanAttributes - ash_lichte Raumhöhe: 2.500000; RoomName: Flur
 | WUN-H2-E01-073 | CLADDING | 49 0.001 m | 1166Sfl0000667733/01 | m² | Maler- und Lackierarbeiten | 1 | 0.001 | 0 | 1 | Seitenfläche | 49 | 150 | 3150 | NEW
Gipsfaserplatten 2-lagig (BSK) | WUN-H2-E01-073 | CEILING | layer 0.036 m | 1166Dfl0000229335/01 | m² | Trockenbauarbeiten | 1 | 0.036 | 0 | 1 | Deckenfläche |  | 0 | 0 | NEW | 2.5 | AllplanAttributes - Bezeichnung: Gipsfaserplatten 2-lagig (BSK); RoomName: Dienstraum Pflege
Gipsfaserplatten 2-lagig (BSK) | WUN-H2-E01-073 | CEILING | Installationshöhe 0.714 m | 1166Dfl0000229335/02 | m² | Trockenbauarbeiten | 2 | 0.714 | 0 | 1 | Bekleidung | Installationshöhe | 0 | 0 | NEW | 2.5 | AllplanAttributes - ash_lichte Raumhöhe: 2.500000; RoomName: Dienstraum Pflege
Gipsfaserplatten 2-lagig (BSK) | WUN-H2-E01-073 | CEILING | Aa 0.15 m | 1166Dfl0000229335/03 | m² | Trockenbauarbeiten | 3 | 0.15 | 0 | 1 | Bekleidung | Aa | 0 | 0 | NEW | 2.5 | AllplanAttributes - ash_lichte Raumhöhe: 2.500000; RoomName: Dienstraum Pflege; Pset_CoveringCommon - AcousticRating: -
Gipsfaserplatten 2-lagig (BSK) | WUN-H2-E01-073 | CEILING | D1 0.001 m | 1166Dfl0000229335/04 | m² | Maler- und Lackierarbeiten | 4 | 0.001 | 0 | 1 | Bekleidung | D1 | 0 | 0 | NEW | 2.5 | AllplanAttributes - ash_lichte Raumhöhe: 2.500000; RoomName: Dienstraum Pflege
PVC Bahnenware Holzoptik | WUN-H2-E01-073 | FLOORING | Ku1 0.15 m | 1166Bfl0000034179/01 | m² | Bodenbelagsarbeiten | 1 | 0.15 | 0 | 1 | Bodenfläche | Ku1 | 0 | 0 | NEW | AllplanAttributes - Bezeichnung: PVC Bahnenware Holzoptik; Raumnr. Bauherr: 2.11_A2_02; ash B_Aufbau: B9; ash B_Rutschhemmung: R9
Gipsfaserplatten 2-lagig (BSK) | WUN-H2-E01-073 | CEILING | layer 0.036 m | 1166Dfl0000034178/01 | m² | Trockenbauarbeiten | 1 | 0.036 | 0 | 1 | Deckenfläche |  | 0 | 0 | NEW | 2.5 | AllplanAttributes - Bezeichnung: Gipsfaserplatten 2-lagig (BSK); RoomName: Dienstraum Pflege
Gipsfaserplatten 2-lagig (BSK) | WUN-H2-E01-073 | CEILING | Installationshöhe 0.714 m | 1166Dfl0000034178/02 | m² | Trockenbauarbeiten | 2 | 0.714 | 0 | 1 | Bekleidung | Installationshöhe | 0 | 0 | NEW | 2.5 | AllplanAttributes - ash_lichte Raumhöhe: 2.500000; OKFF: 0; RoomName: Dienstraum Pflege
Gipsfaserplatten 2-lagig (BSK) | WUN-H2-E01-073 | CEILING | A1 0.15 m | 1166Dfl0000034178/03 | m² | Trockenbauarbeiten | 3 | 0.15 | 0 | 1 | Bekleidung | A1 | 0 | 0 | NEW | 2.5 | AllplanAttributes - ash_lichte Raumhöhe: 2.500000; OKFF: 0; RoomName: Dienstraum Pflege; Pset_CoveringCommon - AcousticRating: -
Gipsfaserplatten 2-lagig (BSK) | WUN-H2-E01-073 | CEILING | D1 0.001 m | 1166Dfl0000034178/04 | m² | Maler- und Lackierarbeiten | 4 | 0.001 | 0 | 1 | Bekleidung | D1 | 0 | 0 | NEW | 2.5 | AllplanAttributes - ash_lichte Raumhöhe: 2.500000; OKFF: 0; RoomName: Dienstraum Pflege
 | WUN-H2-E01-073 | CLADDING | 49 0.001 m | 1166Sfl0000667732/01 | m² | Maler- und Lackierarbeiten | 1 | 0.001 | 0 | 1 | Seitenfläche | 49 | 150 | 3150 | NEW
Gipsfaserplatten 2-lagig (BSK) | WUN-H2-E01-073 | CEILING | layer 0.036 m | 1166Dfl0000225680/01 | m² | Trockenbauarbeiten | 1 | 0.036 | 0 | 1 | Deckenfläche |  | 0 | 0 | NEW | 2.5 | AllplanAttributes - Bezeichnung: Gipsfaserplatten 2-lagig (BSK); RoomName: Gespräch
Gipsfaserplatten 2-lagig (BSK) | WUN-H2-E01-073 | CEILING | Installationshöhe 0.714 m | 1166Dfl0000225680/02 | m² | Trockenbauarbeiten | 2 | 0.714 | 0 | 1 | Bekleidung | Installationshöhe | 0 | 0 | NEW | 2.5 | AllplanAttributes - ash_lichte Raumhöhe: 2.500000; OKFF: 0; RoomName: Gespräch
Gipsfaserplatten 2-lagig (BSK) | WUN-H2-E01-073 | CEILING | Aa 0.15 m | 1166Dfl0000225680/03 | m² | Trockenbauarbeiten | 3 | 0.15 | 0 | 1 | Bekleidung | Aa | 0 | 0 | NEW | 2.5 | AllplanAttributes - ash_lichte Raumhöhe: 2.500000; OKFF: 0; RoomName: Gespräch; Pset_CoveringCommon - AcousticRating: -
Gipsfaserplatten 2-lagig (BSK) | WUN-H2-E01-073 | CEILING | D1 0.001 m | 1166Dfl0000225680/04 | m² | Maler- und Lackierarbeiten | 4 | 0.001 | 0 | 1 | Bekleidung | D1 | 0 | 0 | NEW | 2.5 | AllplanAttributes - ash_lichte Raumhöhe: 2.500000; OKFF: 0; RoomName: Gespräch
Gipsfaserplatten 2-lagig (BSK) | WUN-H2-E01-073 | CEILING | layer 0.036 m | 1166Dfl0000033133/01 | m² | Trockenbauarbeiten | 1 | 0.036 | 0 | 1 | Deckenfläche |  | 0 | 0 | NEW | 2.5 | AllplanAttributes - Bezeichnung: Gipsfaserplatten 2-lagig (BSK); RoomName: Freizeit / Club
Gipsfaserplatten 2-lagig (BSK) | WUN-H2-E01-073 | CEILING | Installationshöhe 0.714 m | 1166Dfl0000033133/02 | m² | Trockenbauarbeiten | 2 | 0.714 | 0 | 1 | Bekleidung | Installationshöhe | 0 | 0 | NEW | 2.5 | AllplanAttributes - ash_lichte Raumhöhe: 2.500000; OKFF: 0; RoomName: Freizeit / Club
Gipsfaserplatten 2-lagig (BSK) | WUN-H2-E01-073 | CEILING | A1 0.15 m | 1166Dfl0000033133/03 | m² | Trockenbauarbeiten | 3 | 0.15 | 0 | 1 | Bekleidung | A1 | 0 | 0 | NEW | 2.5 | AllplanAttributes - ash_lichte Raumhöhe: 2.500000; OKFF: 0; RoomName: Freizeit / Club; Pset_CoveringCommon - AcousticRating: -
Gipsfaserplatten 2-lagig (BSK) | WUN-H2-E01-073 | CEILING | D1 0.001 m | 1166Dfl0000033133/04 | m² | Maler- und Lackierarbeiten | 4 | 0.001 | 0 | 1 | Bekleidung | D1 | 0 | 0 | NEW | 2.5 | AllplanAttributes - ash_lichte Raumhöhe: 2.500000; OKFF: 0; RoomName: Freizeit / Club
PVC Bahnenware Holzoptik | WUN-H2-E01-073 | FLOORING | Ku1 0.15 m | 1166Bfl0000033122/01 | m² | Bodenbelagsarbeiten | 1 | 0.15 | 0 | 1 | Bodenfläche | Ku1 | 0 | 0 | NEW | AllplanAttributes - Bezeichnung: PVC Bahnenware Holzoptik; Raumnr. Bauherr: 2.11_A2_02; ash B_Aufbau: B9; ash B_Rutschhemmung: R9
 | WUN-H2-E01-073 | CLADDING | 49 0.001 m | 1166Sfl0000666354/01 | m² | Maler- und Lackierarbeiten | 1 | 0.001 | 0 | 1 | Seitenfläche | 49 | 150 | 3150 | NEW
Gipsfaserplatten 2-lagig (BSK) | WUN-H2-E01-073 | CEILING | layer 0.036 m | 1166Dfl0000225100/01 | m² | Trockenbauarbeiten | 1 | 0.036 | 0 | 1 | Deckenfläche |  | 0 | 0 | NEW | 2.5 | AllplanAttributes - Bezeichnung: Gipsfaserplatten 2-lagig (BSK); RoomName: Gespräch
Gipsfaserplatten 2-lagig (BSK) | WUN-H2-E01-073 | CEILING | Installationshöhe 0.714 m | 1166Dfl0000225100/02 | m² | Trockenbauarbeiten | 2 | 0.714 | 0 | 1 | Bekleidung | Installationshöhe | 0 | 0 | NEW | 2.5 | AllplanAttributes - ash_lichte Raumhöhe: 2.500000; OKFF: 0; RoomName: Gespräch
Gipsfaserplatten 2-lagig (BSK) | WUN-H2-E01-073 | CEILING | Aa 0.15 m | 1166Dfl0000225100/03 | m² | Trockenbauarbeiten | 3 | 0.15 | 0 | 1 | Bekleidung | Aa | 0 | 0 | NEW | 2.5 | AllplanAttributes - ash_lichte Raumhöhe: 2.500000; OKFF: 0; RoomName: Gespräch; Pset_CoveringCommon - AcousticRating: -
Gipsfaserplatten 2-lagig (BSK) | WUN-H2-E01-073 | CEILING | D1 0.001 m | 1166Dfl0000225100/04 | m² | Maler- und Lackierarbeiten | 4 | 0.001 | 0 | 1 | Bekleidung | D1 | 0 | 0 | NEW | 2.5 | AllplanAttributes - ash_lichte Raumhöhe: 2.500000; OKFF: 0; RoomName: Gespräch
Gipsfaserplatten 2-lagig (BSK) | WUN-H2-E01-073 | CEILING | layer 0.036 m | 1166Dfl0000033146/01 | m² | Trockenbauarbeiten | 1 | 0.036 | 0 | 1 | Deckenfläche |  | 0 | 0 | NEW | 2.5 | AllplanAttributes - Bezeichnung: Gipsfaserplatten 2-lagig (BSK); RoomName: Ergo- / Kunsttherapie
Gipsfaserplatten 2-lagig (BSK) | WUN-H2-E01-073 | CEILING | Installationshöhe 0.714 m | 1166Dfl0000033146/02 | m² | Trockenbauarbeiten | 2 | 0.714 | 0 | 1 | Bekleidung | Installationshöhe | 0 | 0 | NEW | 2.5 | AllplanAttributes - ash_lichte Raumhöhe: 2.500000; OKFF: 0; RoomName: Ergo- / Kunsttherapie
Gipsfaserplatten 2-lagig (BSK) | WUN-H2-E01-073 | CEILING | A1 0.15 m | 1166Dfl0000033146/03 | m² | Trockenbauarbeiten | 3 | 0.15 | 0 | 1 | Bekleidung | A1 | 0 | 0 | NEW | 2.5 | AllplanAttributes - ash_lichte Raumhöhe: 2.500000; OKFF: 0; RoomName: Ergo- / Kunsttherapie; Pset_CoveringCommon - AcousticRating: -
Gipsfaserplatten 2-lagig (BSK) | WUN-H2-E01-073 | CEILING | D1 0.001 m | 1166Dfl0000033146/04 | m² | Maler- und Lackierarbeiten | 4 | 0.001 | 0 | 1 | Bekleidung | D1 | 0 | 0 | NEW | 2.5 | AllplanAttributes - ash_lichte Raumhöhe: 2.500000; OKFF: 0; RoomName: Ergo- / Kunsttherapie
PVC Bahnenware Holzoptik | WUN-H2-E01-073 | FLOORING | Ku1 0.15 m | 1166Bfl0000033135/01 | m² | Bodenbelagsarbeiten | 1 | 0.15 | 0 | 1 | Bodenfläche | Ku1 | 0 | 0 | NEW | AllplanAttributes - Bezeichnung: PVC Bahnenware Holzoptik; Raumnr. Bauherr: 2.11_A2_02; ash B_Aufbau: B9; ash B_Rutschhemmung: R9
 | WUN-H2-E01-073 | CLADDING | 49 0.001 m | 1166Sfl0000666353/01 | m² | Maler- und Lackierarbeiten | 1 | 0.001 | 0 | 1 | Seitenfläche | 49 | 150 | 3150 | NEW
PVC Bahnenware Holzoptik | WUN-H2-E01-049 | FLOORING | Ku1 0.15 m | 1166Bfl0000033797/01 | m² | Bodenbelagsarbeiten | 1 | 0.15 | 0 | 1 | Bodenfläche | Ku1 | 0 | 0 | NEW | AllplanAttributes - Bezeichnung: PVC Bahnenware Holzoptik; Raumnr. Bauherr: 2.11_A2_02; ash B_Aufbau: B9; ash B_Rutschhemmung: R9
Gipsfaserplatten 2-lagig (BSK) | WUN-H2-E01-049 | CEILING | layer 0.036 m | 1166Dfl0000033796/01 | m² | Trockenbauarbeiten | 1 | 0.036 | 0 | 1 | Deckenfläche |  | 0 | 0 | NEW | 2.5 | AllplanAttributes - Bezeichnung: Gipsfaserplatten 2-lagig (BSK); RoomName: Speisewagen
Gipsfaserplatten 2-lagig (BSK) | WUN-H2-E01-049 | CEILING | Installationshöhe 0.764 m | 1166Dfl0000033796/02 | m² | Trockenbauarbeiten | 2 | 0.764 | 0 | 1 | Bekleidung | Installationshöhe | 0 | 0 | NEW | 2.5 | AllplanAttributes - ash_lichte Raumhöhe: 2.500000; OKFF: 0; RoomName: Speisewagen
Gipskarton, imprägniert | WUN-H2-E01-049 | CEILING | B 0.1 m | 1166Dfl0000033796/03 | m² | Trockenbauarbeiten | 3 | 0.1 | 0 | 1 | Bekleidung | B | 0 | 0 | NEW | 2.5 | AllplanAttributes - Bezeichnung: Gipskarton, imprägniert; ash_lichte Raumhöhe: 2.500000; OKFF: 0; RoomName: Speisewagen; Pset_CoveringCommon - AcousticRating: -
Gipsfaserplatten 2-lagig (BSK) | WUN-H2-E01-049 | CEILING | D1 0.001 m | 1166Dfl0000033796/04 | m² | Maler- und Lackierarbeiten | 4 | 0.001 | 0 | 1 | Bekleidung | D1 | 0 | 0 | NEW | 2.5 | AllplanAttributes - ash_lichte Raumhöhe: 2.500000; OKFF: 0; RoomName: Speisewagen
 | WUN-H2-E01-049 | CLADDING | 49 0.001 m | 1166Sfl0000667581/01 | m² | Maler- und Lackierarbeiten | 1 | 0.001 | 0 | 1 | Seitenfläche | 49 | 150 | 2500 | NEW
PVC Bahnenware Holzoptik | WUN-H2-E01-F03a | FLOORING | Ku1 0.15 m | 1166Bfl0000034572/01 | m² | Bodenbelagsarbeiten | 1 | 0.15 | 0 | 1 | Bodenfläche | Ku1 | 0 | 0 | NEW | AllplanAttributes - Bezeichnung: PVC Bahnenware Holzoptik; Raumnr. Bauherr: 2.11_A2_02; ash B_Aufbau: B9; ash B_Rutschhemmung: R9
Gipsfaserplatten 2-lagig (BSK) | WUN-H2-E01-F03a | CEILING | layer 0.036 m | 1166Dfl0000034571/01 | m² | Trockenbauarbeiten | 1 | 0.036 | 0 | 1 | Deckenfläche |  | 0 | 0 | NEW | 2.5 | AllplanAttributes - Bezeichnung: Gipsfaserplatten 2-lagig (BSK); RoomName: Marktplatz
Gipsfaserplatten 2-lagig (BSK) | WUN-H2-E01-F03a | CEILING | Installationshöhe 0.714 m | 1166Dfl0000034571/02 | m² | Trockenbauarbeiten | 2 | 0.714 | 0 | 1 | Bekleidung | Installationshöhe | 0 | 0 | NEW | 2.5 | AllplanAttributes - ash_lichte Raumhöhe: 2.500000; RoomName: Marktplatz
Gipsfaserplatten 2-lagig (BSK) | WUN-H2-E01-F03a | CEILING | A1 0.15 m | 1166Dfl0000034571/03 | m² | Trockenbauarbeiten | 3 | 0.15 | 0 | 1 | Bekleidung | A1 | 0 | 0 | NEW | 2.5 | AllplanAttributes - ash_lichte Raumhöhe: 2.500000; RoomName: Marktplatz; Pset_CoveringCommon - AcousticRating: -
Gipsfaserplatten 2-lagig (BSK) | WUN-H2-E01-F03a | CEILING | D1 0.001 m | 1166Dfl0000034571/04 | m² | Maler- und Lackierarbeiten | 4 | 0.001 | 0 | 1 | Bekleidung | D1 | 0 | 0 | NEW | 2.5 | AllplanAttributes - ash_lichte Raumhöhe: 2.500000; RoomName: Marktplatz
Gipsfaserplatten 2-lagig (BSK) | WUN-H2-E01-F03a | CEILING | layer 0.036 m | 1166Dfl0000238977/01 | m² | Trockenbauarbeiten | 1 | 0.036 | 0 | 1 | Deckenfläche |  | 0 | 0 | NEW | 2.5 | AllplanAttributes - Bezeichnung: Gipsfaserplatten 2-lagig (BSK); RoomName: Marktplatz
Gipsfaserplatten 2-lagig (BSK) | WUN-H2-E01-F03a | CEILING | Installationshöhe 0.714 m | 1166Dfl0000238977/02 | m² | Trockenbauarbeiten | 2 | 0.714 | 0 | 1 | Bekleidung | Installationshöhe | 0 | 0 | NEW | 2.5 | AllplanAttributes - ash_lichte Raumhöhe: 2.500000; RoomName: Marktplatz
Gipsfaserplatten 2-lagig (BSK) | WUN-H2-E01-F03a | CEILING | Aa 0.15 m | 1166Dfl0000238977/03 | m² | Trockenbauarbeiten | 3 | 0.15 | 0 | 1 | Bekleidung | Aa | 0 | 0 | NEW | 2.5 | AllplanAttributes - ash_lichte Raumhöhe: 2.500000; RoomName: Marktplatz; Pset_CoveringCommon - AcousticRating: -
Gipsfaserplatten 2-lagig (BSK) | WUN-H2-E01-F03a | CEILING | D1 0.001 m | 1166Dfl0000238977/04 | m² | Maler- und Lackierarbeiten | 4 | 0.001 | 0 | 1 | Bekleidung | D1 | 0 | 0 | NEW | 2.5 | AllplanAttributes - ash_lichte Raumhöhe: 2.500000; RoomName: Marktplatz
 | WUN-H2-E01-F03a | CLADDING | 49 0.001 m | 1166Sfl0000668757/01 | m² | Maler- und Lackierarbeiten | 1 | 0.001 | 0 | 1 | Seitenfläche | 49 | 150 | 2500 | NEW
Gipsfaserplatten 2-lagig (BSK) | WUN-H2-E01-073 | CEILING | layer 0.036 m | 1166Dfl0000227000/01 | m² | Trockenbauarbeiten | 1 | 0.036 | 0 | 1 | Deckenfläche |  | 0 | 0 | NEW | 2.5 | AllplanAttributes - Bezeichnung: Gipsfaserplatten 2-lagig (BSK); RoomName: Marktplatz
Gipsfaserplatten 2-lagig (BSK) | WUN-H2-E01-073 | CEILING | Installationshöhe 0.714 m | 1166Dfl0000227000/02 | m² | Trockenbauarbeiten | 2 | 0.714 | 0 | 1 | Bekleidung | Installationshöhe | 0 | 0 | NEW | 2.5 | AllplanAttributes - ash_lichte Raumhöhe: 2.500000; RoomName: Marktplatz
Gipsfaserplatten 2-lagig (BSK) | WUN-H2-E01-073 | CEILING | Aa 0.15 m | 1166Dfl0000227000/03 | m² | Trockenbauarbeiten | 3 | 0.15 | 0 | 1 | Bekleidung | Aa | 0 | 0 | NEW | 2.5 | AllplanAttributes - ash_lichte Raumhöhe: 2.500000; RoomName: Marktplatz; Pset_CoveringCommon - AcousticRating: -
Gipsfaserplatten 2-lagig (BSK) | WUN-H2-E01-073 | CEILING | D1 0.001 m | 1166Dfl0000227000/04 | m² | Maler- und Lackierarbeiten | 4 | 0.001 | 0 | 1 | Bekleidung | D1 | 0 | 0 | NEW | 2.5 | AllplanAttributes - ash_lichte Raumhöhe: 2.500000; RoomName: Marktplatz
PVC Bahnenware Holzoptik | WUN-H2-E01-073 | FLOORING | Ku1 0.15 m | 1166Bfl0000033267/01 | m² | Bodenbelagsarbeiten | 1 | 0.15 | 0 | 1 | Bodenfläche | Ku1 | 0 | 0 | NEW | AllplanAttributes - Bezeichnung: PVC Bahnenware Holzoptik; Raumnr. Bauherr: 2.11_A2_02; ash B_Aufbau: B9; ash B_Rutschhemmung: R9
Gipsfaserplatten 2-lagig (BSK) | WUN-H2-E01-073 | CEILING | layer 0.036 m | 1166Dfl0000033266/01 | m² | Trockenbauarbeiten | 1 | 0.036 | 0 | 1 | Deckenfläche |  | 0 | 0 | NEW | 2.5 | AllplanAttributes - Bezeichnung: Gipsfaserplatten 2-lagig (BSK); RoomName: Marktplatz
Gipsfaserplatten 2-lagig (BSK) | WUN-H2-E01-073 | CEILING | Installationshöhe 0.714 m | 1166Dfl0000033266/02 | m² | Trockenbauarbeiten | 2 | 0.714 | 0 | 1 | Bekleidung | Installationshöhe | 0 | 0 | NEW | 2.5 | AllplanAttributes - ash_lichte Raumhöhe: 2.500000; RoomName: Marktplatz
Gipsfaserplatten 2-lagig (BSK) | WUN-H2-E01-073 | CEILING | A1 0.15 m | 1166Dfl0000033266/03 | m² | Trockenbauarbeiten | 3 | 0.15 | 0 | 1 | Bekleidung | A1 | 0 | 0 | NEW | 2.5 | AllplanAttributes - ash_lichte Raumhöhe: 2.500000; RoomName: Marktplatz; Pset_CoveringCommon - AcousticRating: -
Gipsfaserplatten 2-lagig (BSK) | WUN-H2-E01-073 | CEILING | D1 0.001 m | 1166Dfl0000033266/04 | m² | Maler- und Lackierarbeiten | 4 | 0.001 | 0 | 1 | Bekleidung | D1 | 0 | 0 | NEW | 2.5 | AllplanAttributes - ash_lichte Raumhöhe: 2.500000; RoomName: Marktplatz
 | WUN-H2-E01-073 | CLADDING | 49 0.001 m | 1166Sfl0000668528/01 | m² | Maler- und Lackierarbeiten | 1 | 0.001 | 0 | 1 | Seitenfläche | 49 | 150 | 3150 | NEW
Fliesen | WUN-H2-E01-062 | FLOORING | Fl1 0.15 m | 1166Bfl0000034167/01 | m² | Bodenbelagsarbeiten | 1 | 0.15 | 0 | 1 | Bodenfläche | Fl1 | 0 | 0 | NEW | AllplanAttributes - Bezeichnung: Fliesen; Raumnr. Bauherr: 2.11_A2_02; ash B_Aufbau: B10; ash B_Rutschhemmung: R10
Gipsfaserplatten 2-lagig (BSK) | WUN-H2-E01-062 | CEILING | layer 0.036 m | 1166Dfl0000034168/01 | m² | Trockenbauarbeiten | 1 | 0.036 | 0 | 1 | Deckenfläche |  | 0 | 0 | NEW | 2.5 | AllplanAttributes - Bezeichnung: Gipsfaserplatten 2-lagig (BSK); RoomName: WC Bes. rsg.
Gipsfaserplatten 2-lagig (BSK) | WUN-H2-E01-062 | CEILING | Installationshöhe 0.764 m | 1166Dfl0000034168/02 | m² | Trockenbauarbeiten | 2 | 0.764 | 0 | 1 | Bekleidung | Installationshöhe | 0 | 0 | NEW | 2.5 | AllplanAttributes - ash_lichte Raumhöhe: 2.500000; OKFF: 0; RoomName: WC Bes. rsg.
Gipskarton, imprägniert | WUN-H2-E01-062 | CEILING | B 0.1 m | 1166Dfl0000034168/03 | m² | Trockenbauarbeiten | 3 | 0.1 | 0 | 1 | Bekleidung | B | 0 | 0 | NEW | 2.5 | AllplanAttributes - Bezeichnung: Gipskarton, imprägniert; ash_lichte Raumhöhe: 2.500000; OKFF: 0; RoomName: WC Bes. rsg.; Pset_CoveringCommon - AcousticRating: -
Gipsfaserplatten 2-lagig (BSK) | WUN-H2-E01-062 | CEILING | D1 0.001 m | 1166Dfl0000034168/04 | m² | Maler- und Lackierarbeiten | 4 | 0.001 | 0 | 1 | Bekleidung | D1 | 0 | 0 | NEW | 2.5 | AllplanAttributes - ash_lichte Raumhöhe: 2.500000; OKFF: 0; RoomName: WC Bes. rsg.
 | WUN-H2-E01-062 | CLADDING | 50 0.001 m | 1166Sfl0000668529/01 | m² | Maler- und Lackierarbeiten | 1 | 0.001 | 0 | 1 | Seitenfläche | 50 | 150 | 2500 | NEW
a-sh Wandbelag | WUN-H2-E01-062 | CLADDING | 65 0.01 m | 1166Sfl0000668530/01 | m² | Maler- und Lackierarbeiten | 1 | 0.01 | 0 | 1 | Seitenfläche | 65 | 100 | 3000 | NEW | AllplanAttributes - Bezeichnung: a-sh Wandbelag; Attributset-Objekt: Covering
PVC Bahnenware Holzoptik | WUN-H2-E01-073 | FLOORING | Ku1 0.15 m | 1166Bfl0000034206/01 | m² | Bodenbelagsarbeiten | 1 | 0.15 | 0 | 1 | Bodenfläche | Ku1 | 0 | 0 | NEW | AllplanAttributes - Bezeichnung: PVC Bahnenware Holzoptik; Raumnr. Bauherr: 2.11_A2_02; ash B_Aufbau: B9; ash B_Rutschhemmung: R9
Gipsfaserplatten 2-lagig (BSK) | WUN-H2-E01-073 | CEILING | layer 0.036 m | 1166Dfl0000034205/01 | m² | Trockenbauarbeiten | 1 | 0.036 | 0 | 1 | Deckenfläche |  | 0 | 0 | NEW | 2.5 | AllplanAttributes - Bezeichnung: Gipsfaserplatten 2-lagig (BSK); RoomName: Marktplatz
Gipsfaserplatten 2-lagig (BSK) | WUN-H2-E01-073 | CEILING | Installationshöhe 0.714 m | 1166Dfl0000034205/02 | m² | Trockenbauarbeiten | 2 | 0.714 | 0 | 1 | Bekleidung | Installationshöhe | 0 | 0 | NEW | 2.5 | AllplanAttributes - ash_lichte Raumhöhe: 2.500000; RoomName: Marktplatz
Gipsfaserplatten 2-lagig (BSK) | WUN-H2-E01-073 | CEILING | A1 0.15 m | 1166Dfl0000034205/03 | m² | Trockenbauarbeiten | 3 | 0.15 | 0 | 1 | Bekleidung | A1 | 0 | 0 | NEW | 2.5 | AllplanAttributes - ash_lichte Raumhöhe: 2.500000; RoomName: Marktplatz; Pset_CoveringCommon - AcousticRating: -
Gipsfaserplatten 2-lagig (BSK) | WUN-H2-E01-073 | CEILING | D1 0.001 m | 1166Dfl0000034205/04 | m² | Maler- und Lackierarbeiten | 4 | 0.001 | 0 | 1 | Bekleidung | D1 | 0 | 0 | NEW | 2.5 | AllplanAttributes - ash_lichte Raumhöhe: 2.500000; RoomName: Marktplatz
 | WUN-H2-E01-073 | CLADDING | 49 0.001 m | 1166Sfl0000668527/01 | m² | Maler- und Lackierarbeiten | 1 | 0.001 | 0 | 1 | Seitenfläche | 49 | 150 | 3150 | NEW
Gipsfaserplatten 2-lagig (BSK) | WUN-H2-E01-073 | CEILING | layer 0.036 m | 1166Dfl0000229915/01 | m² | Trockenbauarbeiten | 1 | 0.036 | 0 | 1 | Deckenfläche |  | 0 | 0 | NEW | 2.5 | AllplanAttributes - Bezeichnung: Gipsfaserplatten 2-lagig (BSK); RoomName: Marktplatz
Gipsfaserplatten 2-lagig (BSK) | WUN-H2-E01-073 | CEILING | Installationshöhe 0.714 m | 1166Dfl0000229915/02 | m² | Trockenbauarbeiten | 2 | 0.714 | 0 | 1 | Bekleidung | Installationshöhe | 0 | 0 | NEW | 2.5 | AllplanAttributes - ash_lichte Raumhöhe: 2.500000; RoomName: Marktplatz
Gipsfaserplatten 2-lagig (BSK) | WUN-H2-E01-073 | CEILING | Aa 0.15 m | 1166Dfl0000229915/03 | m² | Trockenbauarbeiten | 3 | 0.15 | 0 | 1 | Bekleidung | Aa | 0 | 0 | NEW | 2.5 | AllplanAttributes - ash_lichte Raumhöhe: 2.500000; RoomName: Marktplatz; Pset_CoveringCommon - AcousticRating: -
Gipsfaserplatten 2-lagig (BSK) | WUN-H2-E01-073 | CEILING | D1 0.001 m | 1166Dfl0000229915/04 | m² | Maler- und Lackierarbeiten | 4 | 0.001 | 0 | 1 | Bekleidung | D1 | 0 | 0 | NEW | 2.5 | AllplanAttributes - ash_lichte Raumhöhe: 2.500000; RoomName: Marktplatz
PVC Bahnenware Holzoptik | WUN-H2-E01-F09a | FLOORING | Ku1 0.15 m | 1166Bfl0000034561/01 | m² | Bodenbelagsarbeiten | 1 | 0.15 | 0 | 1 | Bodenfläche | Ku1 | 0 | 0 | NEW | AllplanAttributes - Bezeichnung: PVC Bahnenware Holzoptik; Raumnr. Bauherr: 2.11_A2_02; ash B_Aufbau: B9; ash B_Rutschhemmung: R9
Gipsfaserplatten 2-lagig (BSK) | WUN-H2-E01-F09a | CEILING | layer 0.036 m | 1166Dfl0000239557/01 | m² | Trockenbauarbeiten | 1 | 0.036 | 0 | 1 | Deckenfläche |  | 0 | 0 | NEW | 2.5 | AllplanAttributes - Bezeichnung: Gipsfaserplatten 2-lagig (BSK); RoomName: Marktplatz
Gipsfaserplatten 2-lagig (BSK) | WUN-H2-E01-F09a | CEILING | Installationshöhe 0.714 m | 1166Dfl0000239557/02 | m² | Trockenbauarbeiten | 2 | 0.714 | 0 | 1 | Bekleidung | Installationshöhe | 0 | 0 | NEW | 2.5 | AllplanAttributes - ash_lichte Raumhöhe: 2.500000; RoomName: Marktplatz
Gipsfaserplatten 2-lagig (BSK) | WUN-H2-E01-F09a | CEILING | Aa 0.15 m | 1166Dfl0000239557/03 | m² | Trockenbauarbeiten | 3 | 0.15 | 0 | 1 | Bekleidung | Aa | 0 | 0 | NEW | 2.5 | AllplanAttributes - ash_lichte Raumhöhe: 2.500000; RoomName: Marktplatz; Pset_CoveringCommon - AcousticRating: -
Gipsfaserplatten 2-lagig (BSK) | WUN-H2-E01-F09a | CEILING | D1 0.001 m | 1166Dfl0000239557/04 | m² | Maler- und Lackierarbeiten | 4 | 0.001 | 0 | 1 | Bekleidung | D1 | 0 | 0 | NEW | 2.5 | AllplanAttributes - ash_lichte Raumhöhe: 2.500000; RoomName: Marktplatz
Gipsfaserplatten 2-lagig (BSK) | WUN-H2-E01-F09a | CEILING | layer 0.036 m | 1166Dfl0000034560/01 | m² | Trockenbauarbeiten | 1 | 0.036 | 0 | 1 | Deckenfläche |  | 0 | 0 | NEW | 2.5 | AllplanAttributes - Bezeichnung: Gipsfaserplatten 2-lagig (BSK); RoomName: Marktplatz
Gipsfaserplatten 2-lagig (BSK) | WUN-H2-E01-F09a | CEILING | Installationshöhe 0.714 m | 1166Dfl0000034560/02 | m² | Trockenbauarbeiten | 2 | 0.714 | 0 | 1 | Bekleidung | Installationshöhe | 0 | 0 | NEW | 2.5 | AllplanAttributes - ash_lichte Raumhöhe: 2.500000; RoomName: Marktplatz
Gipsfaserplatten 2-lagig (BSK) | WUN-H2-E01-F09a | CEILING | A1 0.15 m | 1166Dfl0000034560/03 | m² | Trockenbauarbeiten | 3 | 0.15 | 0 | 1 | Bekleidung | A1 | 0 | 0 | NEW | 2.5 | AllplanAttributes - ash_lichte Raumhöhe: 2.500000; RoomName: Marktplatz; Pset_CoveringCommon - AcousticRating: -
Gipsfaserplatten 2-lagig (BSK) | WUN-H2-E01-F09a | CEILING | D1 0.001 m | 1166Dfl0000034560/04 | m² | Maler- und Lackierarbeiten | 4 | 0.001 | 0 | 1 | Bekleidung | D1 | 0 | 0 | NEW | 2.5 | AllplanAttributes - ash_lichte Raumhöhe: 2.500000; RoomName: Marktplatz
 | WUN-H2-E01-F09a | CLADDING | 49 0.001 m | 1166Sfl0000668753/01 | m² | Maler- und Lackierarbeiten | 1 | 0.001 | 0 | 1 | Seitenfläche | 49 | 150 | 2500 | NEW
Gipsfaserplatten 2-lagig (BSK) | WUN-H2-E01-008 | CEILING | layer 0.036 m | 1166Dfl0000277717/01 | m² | Trockenbauarbeiten | 1 | 0.036 | 0 | 1 | Deckenfläche |  | 0 | 0 | NEW | 2.75 | AllplanAttributes - Bezeichnung: Gipsfaserplatten 2-lagig (BSK); RoomName: Speiseraum
Gipsfaserplatten 2-lagig (BSK) | WUN-H2-E01-008 | CEILING | Installationshöhe 0.424 m | 1166Dfl0000277717/02 | m² | Trockenbauarbeiten | 2 | 0.424 | 0 | 1 | Bekleidung | Installationshöhe | 0 | 0 | NEW | 2.75 | AllplanAttributes - ash_lichte Raumhöhe: 2.750000; OKFF: 0; RoomName: Speiseraum
Gipsfaserplatten 2-lagig (BSK) | WUN-H2-E01-008 | CEILING | A1 0.15 m | 1166Dfl0000277717/03 | m² | Trockenbauarbeiten | 3 | 0.15 | 0 | 1 | Bekleidung | A1 | 0 | 0 | NEW | 2.75 | AllplanAttributes - ash_lichte Raumhöhe: 2.750000; OKFF: 0; RoomName: Speiseraum; Pset_CoveringCommon - AcousticRating: -
Gipsfaserplatten 2-lagig (BSK) | WUN-H2-E01-008 | CEILING | D1 0.001 m | 1166Dfl0000277717/04 | m² | Maler- und Lackierarbeiten | 4 | 0.001 | 0 | 1 | Bekleidung | D1 | 0 | 0 | NEW | 2.75 | AllplanAttributes - ash_lichte Raumhöhe: 2.750000; OKFF: 0; RoomName: Speiseraum
Gipsfaserplatten 2-lagig (BSK) | WUN-H2-E01-008 | CEILING | layer 0.036 m | 1166Dfl0000278512/01 | m² | Trockenbauarbeiten | 1 | 0.036 | 0 | 1 | Deckenfläche |  | 0 | 0 | NEW | 2.75 | AllplanAttributes - Bezeichnung: Gipsfaserplatten 2-lagig (BSK); RoomName: Speiseraum
Gipsfaserplatten 2-lagig (BSK) | WUN-H2-E01-008 | CEILING | Installationshöhe 0.464 m | 1166Dfl0000278512/02 | m² | Trockenbauarbeiten | 2 | 0.464 | 0 | 1 | Bekleidung | Installationshöhe | 0 | 0 | NEW | 2.75 | AllplanAttributes - ash_lichte Raumhöhe: 2.750000; OKFF: 0; RoomName: Speiseraum
Gipsfaserplatten 2-lagig (BSK) | WUN-H2-E01-008 | CEILING | A1 0.15 m | 1166Dfl0000278512/03 | m² | Trockenbauarbeiten | 3 | 0.15 | 0 | 1 | Bekleidung | A1 | 0 | 0 | NEW | 2.75 | AllplanAttributes - ash_lichte Raumhöhe: 2.750000; OKFF: 0; RoomName: Speiseraum; Pset_CoveringCommon - AcousticRating: -
Gipsfaserplatten 2-lagig (BSK) | WUN-H2-E01-008 | CEILING | D1 0.001 m | 1166Dfl0000278512/04 | m² | Maler- und Lackierarbeiten | 4 | 0.001 | 0 | 1 | Bekleidung | D1 | 0 | 0 | NEW | 2.75 | AllplanAttributes - ash_lichte Raumhöhe: 2.750000; OKFF: 0; RoomName: Speiseraum
Gipsfaserplatten 2-lagig (BSK) | WUN-H2-E01-008 | CEILING | layer 0.036 m | 1166Dfl0000277718/01 | m² | Trockenbauarbeiten | 1 | 0.036 | 0 | 1 | Deckenfläche |  | 0 | 0 | NEW | 2.75 | AllplanAttributes - Bezeichnung: Gipsfaserplatten 2-lagig (BSK); RoomName: Speiseraum
Gipsfaserplatten 2-lagig (BSK) | WUN-H2-E01-008 | CEILING | Installationshöhe 0.424 m | 1166Dfl0000277718/02 | m² | Trockenbauarbeiten | 2 | 0.424 | 0 | 1 | Bekleidung | Installationshöhe | 0 | 0 | NEW | 2.75 | AllplanAttributes - ash_lichte Raumhöhe: 2.750000; OKFF: 0; RoomName: Speiseraum
Gipsfaserplatten 2-lagig (BSK) | WUN-H2-E01-008 | CEILING | Aa 0.15 m | 1166Dfl0000277718/03 | m² | Trockenbauarbeiten | 3 | 0.15 | 0 | 1 | Bekleidung | Aa | 0 | 0 | NEW | 2.75 | AllplanAttributes - ash_lichte Raumhöhe: 2.750000; OKFF: 0; RoomName: Speiseraum; Pset_CoveringCommon - AcousticRating: -
Gipsfaserplatten 2-lagig (BSK) | WUN-H2-E01-008 | CEILING | D1 0.001 m | 1166Dfl0000277718/04 | m² | Maler- und Lackierarbeiten | 4 | 0.001 | 0 | 1 | Bekleidung | D1 | 0 | 0 | NEW | 2.75 | AllplanAttributes - ash_lichte Raumhöhe: 2.750000; OKFF: 0; RoomName: Speiseraum
Gipsfaserplatten 2-lagig (BSK) | WUN-H2-E01-008 | CEILING | layer 0.036 m | 1166Dfl0000278510/01 | m² | Trockenbauarbeiten | 1 | 0.036 | 0 | 1 | Deckenfläche |  | 0 | 0 | NEW | 2.75 | AllplanAttributes - Bezeichnung: Gipsfaserplatten 2-lagig (BSK); RoomName: Speiseraum
Gipsfaserplatten 2-lagig (BSK) | WUN-H2-E01-008 | CEILING | Installationshöhe 0.464 m | 1166Dfl0000278510/02 | m² | Trockenbauarbeiten | 2 | 0.464 | 0 | 1 | Bekleidung | Installationshöhe | 0 | 0 | NEW | 2.75 | AllplanAttributes - ash_lichte Raumhöhe: 2.750000; OKFF: 0; RoomName: Speiseraum
Gipsfaserplatten 2-lagig (BSK) | WUN-H2-E01-008 | CEILING | Aa 0.15 m | 1166Dfl0000278510/03 | m² | Trockenbauarbeiten | 3 | 0.15 | 0 | 1 | Bekleidung | Aa | 0 | 0 | NEW | 2.75 | AllplanAttributes - ash_lichte Raumhöhe: 2.750000; OKFF: 0; RoomName: Speiseraum; Pset_CoveringCommon - AcousticRating: -
Gipsfaserplatten 2-lagig (BSK) | WUN-H2-E01-008 | CEILING | D1 0.001 m | 1166Dfl0000278510/04 | m² | Maler- und Lackierarbeiten | 4 | 0.001 | 0 | 1 | Bekleidung | D1 | 0 | 0 | NEW | 2.75 | AllplanAttributes - ash_lichte Raumhöhe: 2.750000; OKFF: 0; RoomName: Speiseraum
Gipsfaserplatten 2-lagig (BSK) | WUN-H2-E01-008 | CEILING | layer 0.036 m | 1166Dfl0000278518/01 | m² | Trockenbauarbeiten | 1 | 0.036 | 0 | 1 | Deckenfläche |  | 0 | 0 | NEW | 3.1 | AllplanAttributes - Bezeichnung: Gipsfaserplatten 2-lagig (BSK); RoomName: Speiseraum
Gipsfaserplatten 2-lagig (BSK) | WUN-H2-E01-008 | CEILING | Installationshöhe 0.124 m | 1166Dfl0000278518/02 | m² | Trockenbauarbeiten | 2 | 0.124 | 0 | 1 | Bekleidung | Installationshöhe | 0 | 0 | NEW | 3.1 | AllplanAttributes - ash_lichte Raumhöhe: 3.100000; OKFF: 0; RoomName: Speiseraum
Gipsfaserplatten 2-lagig (BSK) | WUN-H2-E01-008 | CEILING | A1 0.1 m | 1166Dfl0000278518/03 | m² | Trockenbauarbeiten | 3 | 0.1 | 0 | 1 | Bekleidung | A1 | 0 | 0 | NEW | 3.1 | AllplanAttributes - ash_lichte Raumhöhe: 3.100000; OKFF: 0; RoomName: Speiseraum; Pset_CoveringCommon - AcousticRating: -
Gipsfaserplatten 2-lagig (BSK) | WUN-H2-E01-008 | CEILING | D1 0.001 m | 1166Dfl0000278518/04 | m² | Maler- und Lackierarbeiten | 4 | 0.001 | 0 | 1 | Bekleidung | D1 | 0 | 0 | NEW | 3.1 | AllplanAttributes - ash_lichte Raumhöhe: 3.100000; OKFF: 0; RoomName: Speiseraum
PVC Bahnenware Holzoptik | WUN-H2-E01-008 | FLOORING | Ku1 0.15 m | 1166Bfl0000033174/01 | m² | Bodenbelagsarbeiten | 1 | 0.15 | 0 | 1 | Bodenfläche | Ku1 | 0 | 0 | NEW | AllplanAttributes - Bezeichnung: PVC Bahnenware Holzoptik; Raumnr. Bauherr: 2.11_A2_02; ash B_Aufbau: B9; ash B_Rutschhemmung: R9
Gipsfaserplatten 2-lagig (BSK) | WUN-H2-E01-008 | CEILING | layer 0.036 m | 1166Dfl0000033175/01 | m² | Trockenbauarbeiten | 1 | 0.036 | 0 | 1 | Deckenfläche |  | 0 | 0 | NEW | 3.1 | AllplanAttributes - Bezeichnung: Gipsfaserplatten 2-lagig (BSK); RoomName: Sprechzimmer
Gipsfaserplatten 2-lagig (BSK) | WUN-H2-E01-008 | CEILING | Installationshöhe 0.164 m | 1166Dfl0000033175/02 | m² | Trockenbauarbeiten | 2 | 0.164 | 0 | 1 | Bekleidung | Installationshöhe | 0 | 0 | NEW | 3.1 | AllplanAttributes - ash_lichte Raumhöhe: 3.100000; RoomName: Sprechzimmer; Pset_CoveringCommon - AcousticRating: -
Gipsfaserplatten 2-lagig (BSK) | WUN-H2-E01-008 | CEILING | A1 0.1 m | 1166Dfl0000033175/03 | m² | Trockenbauarbeiten | 3 | 0.1 | 0 | 1 | Bekleidung | A1 | 0 | 0 | NEW | 3.1 | AllplanAttributes - ash_lichte Raumhöhe: 3.100000; RoomName: Sprechzimmer; Pset_CoveringCommon - AcousticRating: -
Gipsfaserplatten 2-lagig (BSK) | WUN-H2-E01-008 | CEILING | D1 0.001 m | 1166Dfl0000033175/04 | m² | Maler- und Lackierarbeiten | 4 | 0.001 | 0 | 1 | Bekleidung | D1 | 0 | 0 | NEW | 3.1 | AllplanAttributes - ash_lichte Raumhöhe: 3.100000; RoomName: Sprechzimmer
 | WUN-H2-E01-008 | CLADDING | 49 0.001 m | 1166Sfl0000666664/01 | m² | Maler- und Lackierarbeiten | 1 | 0.001 | 0 | 1 | Seitenfläche | 49 | 150 | 2750 | NEW
Estrich | H2 Ebene 0 | FLOORING | SE 0.19 m | 1115Bfl0813977422/01 | m² | Bodenbelagsarbeiten | 1 | 0.19 | 0 | 1 | Bodenfläche | SE | 0 | 0 | NEW | AllplanAttributes - Bezeichnung: Estrich; Raumnr. Bauherr: 2.11_A2_02; ash B_Aufbau: B5
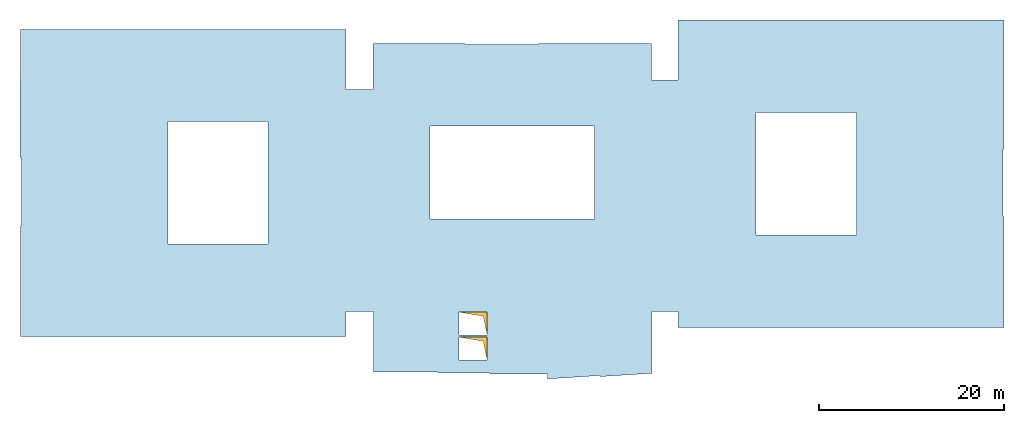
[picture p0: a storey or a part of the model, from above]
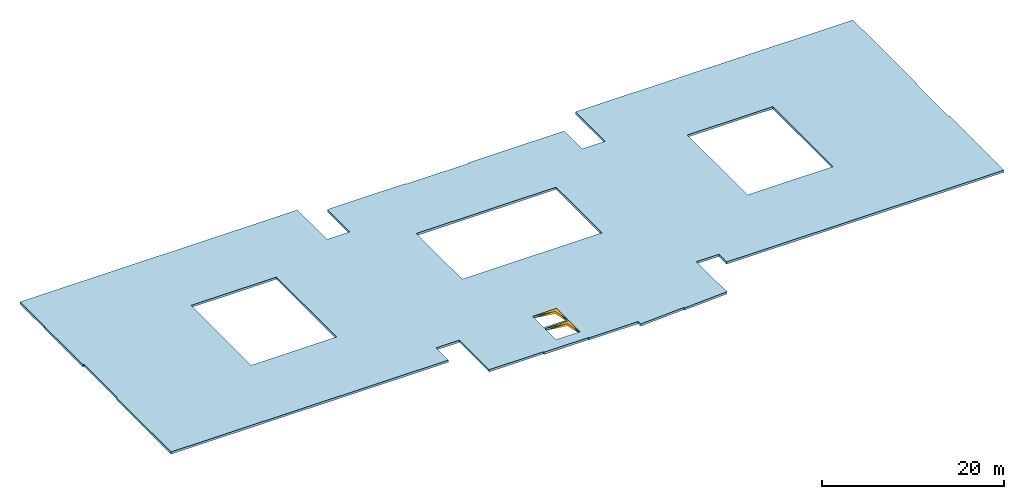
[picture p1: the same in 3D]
Properties of the parts of a building model (IFC4), part 17 of 80

# IfcCovering (3945)
Name | In | PredefinedType | Material | Allright_Bauteil_ID | Abrechnungsart | Gewerk | Schichtnummer | Schichtdicke (m) | Dicke (m) | Faktor | Objektname | AllplanAttributes, Material | Bezugshöhe | Deltahöhe | Status | D_lichte Raumhöhe [Zahl] (m)
Estrich | H2 Ebene 0 | FLOORING | SE 0.19 m | 1115Bfl0813977222/01 | m² | Bodenbelagsarbeiten | 1 | 0.19 | 0 | 1 | Bodenfläche | SE | 0 | 0 | NEW | AllplanAttributes - Bezeichnung: Estrich; Raumnr. Bauherr: 2.11_A2_02; ash B_Aufbau: B5
Estrich | H2 Ebene 0 | FLOORING | SE 0.19 m | 1115Bfl0813977022/01 | m² | Bodenbelagsarbeiten | 1 | 0.19 | 0 | 1 | Bodenfläche | SE | 0 | 0 | NEW | AllplanAttributes - Bezeichnung: Estrich; Raumnr. Bauherr: 2.11_A2_02; ash B_Aufbau: B5
Estrich | H2 Ebene 0 | FLOORING | SE 0.19 m | 1115Bfl0813976822/01 | m² | Bodenbelagsarbeiten | 1 | 0.19 | 0 | 1 | Bodenfläche | SE | 0 | 0 | NEW | AllplanAttributes - Bezeichnung: Estrich; Raumnr. Bauherr: 2.11_A2_02; ash B_Aufbau: B5
Estrich | H2 Ebene 0 | FLOORING | SE 0.19 m | 1115Bfl0813976622/01 | m² | Bodenbelagsarbeiten | 1 | 0.19 | 0 | 1 | Bodenfläche | SE | 0 | 0 | NEW | AllplanAttributes - Bezeichnung: Estrich; Raumnr. Bauherr: 2.11_A2_02; ash B_Aufbau: B5
Estrich | H2 Ebene 0 | FLOORING | SE 0.19 m | 1115Bfl0813976422/01 | m² | Bodenbelagsarbeiten | 1 | 0.19 | 0 | 1 | Bodenfläche | SE | 0 | 0 | NEW | AllplanAttributes - Bezeichnung: Estrich; Raumnr. Bauherr: 2.11_A2_02; ash B_Aufbau: B5
Estrich | H2 Ebene 0 | FLOORING | SE 0.19 m | 1115Bfl0813976222/01 | m² | Bodenbelagsarbeiten | 1 | 0.19 | 0 | 1 | Bodenfläche | SE | 0 | 0 | NEW | AllplanAttributes - Bezeichnung: Estrich; Raumnr. Bauherr: 2.11_A2_02; ash B_Aufbau: B5
Estrich | H2 Ebene 0 | FLOORING | SE 0.19 m | 1115Bfl0813976022/01 | m² | Bodenbelagsarbeiten | 1 | 0.19 | 0 | 1 | Bodenfläche | SE | 0 | 0 | NEW | AllplanAttributes - Bezeichnung: Estrich; Raumnr. Bauherr: 2.11_A2_02; ash B_Aufbau: B5
a-sh Abschluss Abhangdecke | H2 Ebene 0 | CEILING | D1 | 1115HWa0813979849 | m² |  |  |  |  |  | Gesamtwand |  |  |  | NEW | AllplanAttributes - Bezeichnung: a-sh Abschluss Abhangdecke; Attributset-Objekt: Covering; Object Layer Attributes #1, 2D Interaktion: yes; Object Layer Attributes #1, Gewerk: Trockenbauarbeiten; Object Layer Attributes #1, Material: A; Object Layer Attributes #1, Attributset-Objekt: Covering; Object Layer Attributes #1, Allright_Bauteil_ID: 1115Wa 0813979850; Object Layer Attributes #1, Abrechnungsart: m²; Object Layer Attributes #1, Objektname: Wand; Pset_CoveringCommon - IsExternal: no; FireRating: -; ThermalTransmittance: 0 W/K/m2; Reference: Reference
a-sh Abschluss Abhangdecke | H2 Ebene 0 | CEILING |  | 1115HWa0813979854 | m² |  |  |  |  |  | Gesamtwand |  |  |  | NEW | AllplanAttributes - Bezeichnung: a-sh Abschluss Abhangdecke; Attributset-Objekt: Covering; Object Layer Attributes #1, 2D Interaktion: yes; Object Layer Attributes #1, Gewerk: Trockenbauarbeiten; Object Layer Attributes #1, Material: A; Object Layer Attributes #1, Attributset-Objekt: Covering; Object Layer Attributes #1, Allright_Bauteil_ID: 1115Wa 0813979855; Object Layer Attributes #1, Abrechnungsart: m²; Object Layer Attributes #1, Objektname: Wand; Pset_CoveringCommon - IsExternal: no; FireRating: -; ThermalTransmittance: 0 W/K/m2; Reference: Reference
a-sh Abschluss Abhangdecke | H2 Ebene 0 | CEILING |  | 1115HWa0813979870 | m² |  |  |  |  |  | Gesamtwand |  |  |  | NEW | AllplanAttributes - Bezeichnung: a-sh Abschluss Abhangdecke; Attributset-Objekt: Covering; Object Layer Attributes #1, 2D Interaktion: yes; Object Layer Attributes #1, Gewerk: Trockenbauarbeiten; Object Layer Attributes #1, Material: A; Object Layer Attributes #1, Attributset-Objekt: Covering; Object Layer Attributes #1, Allright_Bauteil_ID: 1115Wa 0813979871; Object Layer Attributes #1, Abrechnungsart: m²; Object Layer Attributes #1, Objektname: Wand; Pset_CoveringCommon - IsExternal: no; FireRating: -; ThermalTransmittance: 0 W/K/m2; Reference: Reference
a-sh Abschluss Abhangdecke | H2 Ebene 0 | CEILING |  | 1115HWa0813979875 | m² |  |  |  |  |  | Gesamtwand |  |  |  | NEW | AllplanAttributes - Bezeichnung: a-sh Abschluss Abhangdecke; Attributset-Objekt: Covering; Object Layer Attributes #1, 2D Interaktion: yes; Object Layer Attributes #1, Gewerk: Trockenbauarbeiten; Object Layer Attributes #1, Material: A; Object Layer Attributes #1, Attributset-Objekt: Covering; Object Layer Attributes #1, Allright_Bauteil_ID: 1115Wa 0813979876; Object Layer Attributes #1, Abrechnungsart: m²; Object Layer Attributes #1, Objektname: Wand; Pset_CoveringCommon - IsExternal: no; FireRating: -; ThermalTransmittance: 0 W/K/m2; Reference: Reference
a-sh Abschluss Abhangdecke | H2 Ebene 0 | CEILING |  | 1115HWa0813979885 | m² |  |  |  |  |  | Gesamtwand |  |  |  | NEW | AllplanAttributes - Bezeichnung: a-sh Abschluss Abhangdecke; Attributset-Objekt: Covering; Object Layer Attributes #1, 2D Interaktion: yes; Object Layer Attributes #1, Gewerk: Trockenbauarbeiten; Object Layer Attributes #1, Material: A; Object Layer Attributes #1, Attributset-Objekt: Covering; Object Layer Attributes #1, Allright_Bauteil_ID: 1115Wa 0813979886; Object Layer Attributes #1, Abrechnungsart: m²; Object Layer Attributes #1, Objektname: Wand; Pset_CoveringCommon - IsExternal: no; FireRating: -; ThermalTransmittance: 0 W/K/m2; Reference: Reference
a-sh Abschluss Abhangdecke | H2 Ebene 0 | CEILING |  | 1115HWa0813979890 | m² |  |  |  |  |  | Gesamtwand |  |  |  | NEW | AllplanAttributes - Bezeichnung: a-sh Abschluss Abhangdecke; Attributset-Objekt: Covering; Object Layer Attributes #1, 2D Interaktion: yes; Object Layer Attributes #1, Gewerk: Trockenbauarbeiten; Object Layer Attributes #1, Material: A; Object Layer Attributes #1, Attributset-Objekt: Covering; Object Layer Attributes #1, Allright_Bauteil_ID: 1115Wa 0813979891; Object Layer Attributes #1, Abrechnungsart: m²; Object Layer Attributes #1, Objektname: Wand; Pset_CoveringCommon - IsExternal: no; FireRating: -; ThermalTransmittance: 0 W/K/m2; Reference: Reference
a-sh Abschluss Abhangdecke | H2 Ebene 0 | CEILING |  | 1115HWa0813979900 | m² |  |  |  |  |  | Gesamtwand |  |  |  | NEW | AllplanAttributes - Bezeichnung: a-sh Abschluss Abhangdecke; Attributset-Objekt: Covering; Object Layer Attributes #1, 2D Interaktion: yes; Object Layer Attributes #1, Gewerk: Trockenbauarbeiten; Object Layer Attributes #1, Material: A; Object Layer Attributes #1, Attributset-Objekt: Covering; Object Layer Attributes #1, Allright_Bauteil_ID: 1115Wa 0813979901; Object Layer Attributes #1, Abrechnungsart: m²; Object Layer Attributes #1, Objektname: Wand; Pset_CoveringCommon - IsExternal: no; FireRating: -; ThermalTransmittance: 0 W/K/m2; Reference: Reference
a-sh Abschluss Abhangdecke | H2 Ebene 0 | CEILING |  | 1115HWa0813979905 | m² |  |  |  |  |  | Gesamtwand |  |  |  | NEW | AllplanAttributes - Bezeichnung: a-sh Abschluss Abhangdecke; Attributset-Objekt: Covering; Object Layer Attributes #1, 2D Interaktion: yes; Object Layer Attributes #1, Gewerk: Trockenbauarbeiten; Object Layer Attributes #1, Material: A; Object Layer Attributes #1, Attributset-Objekt: Covering; Object Layer Attributes #1, Allright_Bauteil_ID: 1115Wa 0813979906; Object Layer Attributes #1, Abrechnungsart: m²; Object Layer Attributes #1, Objektname: Wand; Pset_CoveringCommon - IsExternal: no; FireRating: -; ThermalTransmittance: 0 W/K/m2; Reference: Reference
a-sh Abschluss Abhangdecke | H2 Ebene 0 | CEILING | D1 | 1115HWa0813982508 | m² |  |  |  |  |  | Gesamtwand |  |  |  | NEW | AllplanAttributes - Bezeichnung: a-sh Abschluss Abhangdecke; Attributset-Objekt: Covering; Object Layer Attributes #1, 2D Interaktion: yes; Object Layer Attributes #1, Gewerk: Trockenbauarbeiten; Object Layer Attributes #1, Material: A; Object Layer Attributes #1, Attributset-Objekt: Covering; Object Layer Attributes #1, Allright_Bauteil_ID: 1115Wa 0813982509; Object Layer Attributes #1, Abrechnungsart: m²; Object Layer Attributes #1, Objektname: Wand; Pset_CoveringCommon - IsExternal: no; FireRating: -; ThermalTransmittance: 0 W/K/m2; Reference: Reference
a-sh Abschluss Abhangdecke | H2 Ebene 0 | CEILING | D1 | 1115HWa0813982513 | m² |  |  |  |  |  | Gesamtwand |  |  |  | NEW | AllplanAttributes - Bezeichnung: a-sh Abschluss Abhangdecke; Attributset-Objekt: Covering; Object Layer Attributes #1, 2D Interaktion: yes; Object Layer Attributes #1, Gewerk: Trockenbauarbeiten; Object Layer Attributes #1, Material: A; Object Layer Attributes #1, Attributset-Objekt: Covering; Object Layer Attributes #1, Allright_Bauteil_ID: 1115Wa 0813982514; Object Layer Attributes #1, Abrechnungsart: m²; Object Layer Attributes #1, Objektname: Wand; Pset_CoveringCommon - IsExternal: no; FireRating: -; ThermalTransmittance: 0 W/K/m2; Reference: Reference
a-sh Abschluss Abhangdecke | H2 Ebene 0 | CEILING | D1 | 1115HWa0813982518 | m² |  |  |  |  |  | Gesamtwand |  |  |  | NEW | AllplanAttributes - Bezeichnung: a-sh Abschluss Abhangdecke; Attributset-Objekt: Covering; Object Layer Attributes #1, 2D Interaktion: yes; Object Layer Attributes #1, Gewerk: Trockenbauarbeiten; Object Layer Attributes #1, Material: A; Object Layer Attributes #1, Attributset-Objekt: Covering; Object Layer Attributes #1, Allright_Bauteil_ID: 1115Wa 0813982519; Object Layer Attributes #1, Abrechnungsart: m²; Object Layer Attributes #1, Objektname: Wand; Pset_CoveringCommon - IsExternal: no; FireRating: -; ThermalTransmittance: 0 W/K/m2; Reference: Reference
a-sh Abschluss Abhangdecke | H2 Ebene 0 | CEILING | D1 | 1115HWa0813982523 | m² |  |  |  |  |  | Gesamtwand |  |  |  | NEW | AllplanAttributes - Bezeichnung: a-sh Abschluss Abhangdecke; Attributset-Objekt: Covering; Object Layer Attributes #1, 2D Interaktion: yes; Object Layer Attributes #1, Gewerk: Trockenbauarbeiten; Object Layer Attributes #1, Material: A; Object Layer Attributes #1, Attributset-Objekt: Covering; Object Layer Attributes #1, Allright_Bauteil_ID: 1115Wa 0813982524; Object Layer Attributes #1, Abrechnungsart: m²; Object Layer Attributes #1, Objektname: Wand; Pset_CoveringCommon - IsExternal: no; FireRating: -; ThermalTransmittance: 0 W/K/m2; Reference: Reference
a-sh Abschluss Abhangdecke | H2 Ebene 0 | CEILING |  | 1115HWa0813982528 | m² |  |  |  |  |  | Gesamtwand |  |  |  | NEW | AllplanAttributes - Bezeichnung: a-sh Abschluss Abhangdecke; Attributset-Objekt: Covering; Object Layer Attributes #1, 2D Interaktion: yes; Object Layer Attributes #1, Gewerk: Trockenbauarbeiten; Object Layer Attributes #1, Material: A; Object Layer Attributes #1, Attributset-Objekt: Covering; Object Layer Attributes #1, Allright_Bauteil_ID: 1115Wa 0813982529; Object Layer Attributes #1, Abrechnungsart: m²; Object Layer Attributes #1, Objektname: Wand; Pset_CoveringCommon - IsExternal: no; FireRating: -; ThermalTransmittance: 0 W/K/m2; Reference: Reference
a-sh Abschluss Abhangdecke | H2 Ebene 0 | CEILING |  | 1115HWa0813982538 | m² |  |  |  |  |  | Gesamtwand |  |  |  | NEW | AllplanAttributes - Bezeichnung: a-sh Abschluss Abhangdecke; Attributset-Objekt: Covering; Object Layer Attributes #1, 2D Interaktion: yes; Object Layer Attributes #1, Gewerk: Trockenbauarbeiten; Object Layer Attributes #1, Material: A; Object Layer Attributes #1, Attributset-Objekt: Covering; Object Layer Attributes #1, Allright_Bauteil_ID: 1115Wa 0813982539; Object Layer Attributes #1, Abrechnungsart: m²; Object Layer Attributes #1, Objektname: Wand; Pset_CoveringCommon - IsExternal: no; FireRating: -; ThermalTransmittance: 0 W/K/m2; Reference: Reference
Handlauf | WUN-H2-E00-F10 | CLADDING | 97 0.001 m | 1115Sfl0000092376/02 | m² | Maler- und Lackierarbeiten | 2 | 0.001 | 0 | 1 | Seitenfläche | 97 | 0 | 0 | NEW | AllplanAttributes - Bezeichnung: Handlauf
PVC Bahnenware Holzoptik | WUN-H2-E00-F10 | FLOORING | Ku1 0.2 m | 1115Bfl0000005008/01 | m² | Bodenbelagsarbeiten | 1 | 0.2 | 0 | 1 | Bodenfläche | Ku1 | 0 | 0 | NEW | AllplanAttributes - Bezeichnung: PVC Bahnenware Holzoptik; Raumnr. Bauherr: 2.11_A2_02; ash B_Aufbau: B1; ash B_Rutschhemmung: R9
Gipsfaserplatten 2-lagig (BSK) | WUN-H2-E00-F10 | CEILING | layer 0.036 m | 1115Dfl0000005009/01 | m² | Trockenbauarbeiten | 1 | 0.036 | 0 | 1 | Deckenfläche |  | 0 | 0 | NEW | 2.5 | AllplanAttributes - Bezeichnung: Gipsfaserplatten 2-lagig (BSK)
Gipsfaserplatten 2-lagig (BSK) | WUN-H2-E00-F10 | CEILING | Installationshöhe 0.664 m | 1115Dfl0000005009/02 | m² | Trockenbauarbeiten | 2 | 0.664 | 0 | 1 | Bekleidung | Installationshöhe | 0 | 0 | NEW | 2.5 | Pset_CoveringCommon - FireRating: für korrekte FläVisu; AllplanAttributes - ash_lichte Raumhöhe: 2.500000
Gipsfaserplatten 2-lagig (BSK) | WUN-H2-E00-F10 | CEILING | A1 0.2 m | 1115Dfl0000005009/03 | m² | Trockenbauarbeiten | 3 | 0.2 | 0 | 1 | Bekleidung | A1 | 0 | 0 | NEW | 2.5 | Pset_CoveringCommon - FireRating: F30; AcousticRating: -; AllplanAttributes - ash_lichte Raumhöhe: 2.500000
Gipsfaserplatten 2-lagig (BSK) | WUN-H2-E00-F10 | CEILING | D1 0.001 m | 1115Dfl0000005009/04 | m² | Maler- und Lackierarbeiten | 4 | 0.001 | 0 | 1 | Bekleidung | D1 | 0 | 0 | NEW | 2.5 | AllplanAttributes - ash_lichte Raumhöhe: 2.500000
Gipsfaserplatten 2-lagig (BSK) | WUN-H2-E00-F10 | CEILING | layer 0.036 m | 1115Dfl0000102219/01 | m² | Trockenbauarbeiten | 1 | 0.036 | 0 | 1 | Deckenfläche |  | 0 | 0 | NEW | 2.5 | AllplanAttributes - Bezeichnung: Gipsfaserplatten 2-lagig (BSK)
Gipsfaserplatten 2-lagig (BSK) | WUN-H2-E00-F10 | CEILING | Installationshöhe 0.664 m | 1115Dfl0000102219/02 | m² | Trockenbauarbeiten | 2 | 0.664 | 0 | 1 | Bekleidung | Installationshöhe | 0 | 0 | NEW | 2.5 | Pset_CoveringCommon - FireRating: für korrekte FläVisu; AllplanAttributes - ash_lichte Raumhöhe: 2.500000
Gipsfaserplatten 2-lagig (BSK) | WUN-H2-E00-F10 | CEILING | Aa 0.2 m | 1115Dfl0000102219/03 | m² | Trockenbauarbeiten | 3 | 0.2 | 0 | 1 | Bekleidung | Aa | 0 | 0 | NEW | 2.5 | Pset_CoveringCommon - FireRating: F30; AcousticRating: -; AllplanAttributes - ash_lichte Raumhöhe: 2.500000
Gipsfaserplatten 2-lagig (BSK) | WUN-H2-E00-F10 | CEILING | D1 0.001 m | 1115Dfl0000102219/04 | m² | Maler- und Lackierarbeiten | 4 | 0.001 | 0 | 1 | Bekleidung | D1 | 0 | 0 | NEW | 2.5 | AllplanAttributes - ash_lichte Raumhöhe: 2.500000
Handlauf | WUN-H2-E00-F05 | CLADDING | 97 0.001 m | 1115Sfl0000093831/02 | m² | Maler- und Lackierarbeiten | 2 | 0.001 | 0 | 1 | Seitenfläche | 97 | 0 | 0 | NEW | AllplanAttributes - Bezeichnung: Handlauf
PVC Bahnenware Holzoptik | WUN-H2-E00-F05 | FLOORING | Ku1 0.2 m | 1115Bfl0000005006/01 | m² | Bodenbelagsarbeiten | 1 | 0.2 | 0 | 1 | Bodenfläche | Ku1 | 0 | 0 | NEW | AllplanAttributes - Bezeichnung: PVC Bahnenware Holzoptik; Raumnr. Bauherr: 2.11_A2_02; ash B_Aufbau: B1; ash B_Rutschhemmung: R9
 | WUN-H2-E00-F05 | SKIRTINGBOARD | 01 | 1115Lei0813974664 | m |  |  |  |  | 1 | Leiste | 01 | 0 | 0 | NEW
Gipsfaserplatten 2-lagig (BSK) | WUN-H2-E00-F05 | CEILING | layer 0.036 m | 1115Dfl0000095318/01 | m² | Trockenbauarbeiten | 1 | 0.036 | 0 | 1 | Deckenfläche |  | 0 | 0 | NEW | 2.5 | AllplanAttributes - Bezeichnung: Gipsfaserplatten 2-lagig (BSK)
Gipsfaserplatten 2-lagig (BSK) | WUN-H2-E00-F05 | CEILING | Installationshöhe 0.664 m | 1115Dfl0000095318/02 | m² | Trockenbauarbeiten | 2 | 0.664 | 0 | 1 | Bekleidung | Installationshöhe | 0 | 0 | NEW | 2.5 | Pset_CoveringCommon - FireRating: für korrekte FläVisu; AllplanAttributes - ash_lichte Raumhöhe: 2.500000
Gipsfaserplatten 2-lagig (BSK) | WUN-H2-E00-F05 | CEILING | Aa 0.2 m | 1115Dfl0000095318/03 | m² | Trockenbauarbeiten | 3 | 0.2 | 0 | 1 | Bekleidung | Aa | 0 | 0 | NEW | 2.5 | Pset_CoveringCommon - FireRating: F30; AcousticRating: -; AllplanAttributes - ash_lichte Raumhöhe: 2.500000
Gipsfaserplatten 2-lagig (BSK) | WUN-H2-E00-F05 | CEILING | D1 0.001 m | 1115Dfl0000095318/04 | m² | Maler- und Lackierarbeiten | 4 | 0.001 | 0 | 1 | Bekleidung | D1 | 0 | 0 | NEW | 2.5 | AllplanAttributes - ash_lichte Raumhöhe: 2.500000
Gipsfaserplatten 2-lagig (BSK) | WUN-H2-E00-F05 | CEILING | layer 0.036 m | 1115Dfl0000005007/01 | m² | Trockenbauarbeiten | 1 | 0.036 | 0 | 1 | Deckenfläche |  | 0 | 0 | NEW | 2.5 | AllplanAttributes - Bezeichnung: Gipsfaserplatten 2-lagig (BSK)
Gipsfaserplatten 2-lagig (BSK) | WUN-H2-E00-F05 | CEILING | Installationshöhe 0.664 m | 1115Dfl0000005007/02 | m² | Trockenbauarbeiten | 2 | 0.664 | 0 | 1 | Bekleidung | Installationshöhe | 0 | 0 | NEW | 2.5 | Pset_CoveringCommon - FireRating: für korrekte FläVisu; AllplanAttributes - ash_lichte Raumhöhe: 2.500000
Gipsfaserplatten 2-lagig (BSK) | WUN-H2-E00-F05 | CEILING | A1 0.2 m | 1115Dfl0000005007/03 | m² | Trockenbauarbeiten | 3 | 0.2 | 0 | 1 | Bekleidung | A1 | 0 | 0 | NEW | 2.5 | Pset_CoveringCommon - FireRating: F30; AcousticRating: -; AllplanAttributes - ash_lichte Raumhöhe: 2.500000
Gipsfaserplatten 2-lagig (BSK) | WUN-H2-E00-F05 | CEILING | D1 0.001 m | 1115Dfl0000005007/04 | m² | Maler- und Lackierarbeiten | 4 | 0.001 | 0 | 1 | Bekleidung | D1 | 0 | 0 | NEW | 2.5 | AllplanAttributes - ash_lichte Raumhöhe: 2.500000
PVC Bahnenware Holzoptik | WUN-H2-E00-F06 | FLOORING | Ku1 0.2 m | 1115Bfl0000005024/01 | m² | Bodenbelagsarbeiten | 1 | 0.2 | 0 | 1 | Bodenfläche | Ku1 | 0 | 0 | NEW | AllplanAttributes - Bezeichnung: PVC Bahnenware Holzoptik; Raumnr. Bauherr: 2.11_A2_02; ash B_Aufbau: B1; ash B_Rutschhemmung: R9
Handlauf | WUN-H2-E00-F06 | CLADDING | 97 0.001 m | 1115Sfl0000157725/02 | m² | Maler- und Lackierarbeiten | 2 | 0.001 | 0 | 1 | Seitenfläche | 97 | 0 | 0 | NEW | AllplanAttributes - Bezeichnung: Handlauf
Handlauf | WUN-H2-E00-F06 | CLADDING | 97 0.001 m | 1115Sfl0000157902/02 | m² | Maler- und Lackierarbeiten | 2 | 0.001 | 0 | 1 | Seitenfläche | 97 | 0 | 0 | NEW | AllplanAttributes - Bezeichnung: Handlauf
Handlauf | WUN-H2-E00-F06 | CLADDING | 97 0.001 m | 1115Sfl0000094704/02 | m² | Maler- und Lackierarbeiten | 2 | 0.001 | 0 | 1 | Seitenfläche | 97 | 0 | 0 | NEW | AllplanAttributes - Bezeichnung: Handlauf
Gipsfaserplatten 2-lagig (BSK) | WUN-H2-E00-F06 | CEILING | layer 0.036 m | 1115Dfl0000096779/01 | m² | Trockenbauarbeiten | 1 | 0.036 | 0 | 1 | Deckenfläche |  | 0 | 0 | NEW | 2.5 | AllplanAttributes - Bezeichnung: Gipsfaserplatten 2-lagig (BSK)
Gipsfaserplatten 2-lagig (BSK) | WUN-H2-E00-F06 | CEILING | Installationshöhe 0.714 m | 1115Dfl0000096779/02 | m² | Trockenbauarbeiten | 2 | 0.714 | 0 | 1 | Bekleidung | Installationshöhe | 0 | 0 | NEW | 2.5 | Pset_CoveringCommon - FireRating: für korrekte FläVisu; AllplanAttributes - ash_lichte Raumhöhe: 2.500000
Gipsfaserplatten 2-lagig (BSK) | WUN-H2-E00-F06 | CEILING | Aa 0.15 m | 1115Dfl0000096779/03 | m² | Trockenbauarbeiten | 3 | 0.15 | 0 | 1 | Bekleidung | Aa | 0 | 0 | NEW | 2.5 | AllplanAttributes - ash_lichte Raumhöhe: 2.500000; Pset_CoveringCommon - AcousticRating: -
Gipsfaserplatten 2-lagig (BSK) | WUN-H2-E00-F06 | CEILING | D1 0.001 m | 1115Dfl0000096779/04 | m² | Maler- und Lackierarbeiten | 4 | 0.001 | 0 | 1 | Bekleidung | D1 | 0 | 0 | NEW | 2.5 | AllplanAttributes - ash_lichte Raumhöhe: 2.500000
Gipsfaserplatten 2-lagig (BSK) | WUN-H2-E00-F06 | CEILING | layer 0.036 m | 1115Dfl0000028558/01 | m² | Trockenbauarbeiten | 1 | 0.036 | 0 | 1 | Deckenfläche |  | 0 | 0 | NEW | 2.5 | AllplanAttributes - Bezeichnung: Gipsfaserplatten 2-lagig (BSK)
Gipsfaserplatten 2-lagig (BSK) | WUN-H2-E00-F06 | CEILING | Installationshöhe 0.714 m | 1115Dfl0000028558/02 | m² | Trockenbauarbeiten | 2 | 0.714 | 0 | 1 | Bekleidung | Installationshöhe | 0 | 0 | NEW | 2.5 | Pset_CoveringCommon - FireRating: für korrekte FläVisu; AllplanAttributes - ash_lichte Raumhöhe: 2.500000
Gipsfaserplatten 2-lagig (BSK) | WUN-H2-E00-F06 | CEILING | A1 0.15 m | 1115Dfl0000028558/03 | m² | Trockenbauarbeiten | 3 | 0.15 | 0 | 1 | Bekleidung | A1 | 0 | 0 | NEW | 2.5 | AllplanAttributes - ash_lichte Raumhöhe: 2.500000; Pset_CoveringCommon - AcousticRating: -
Gipsfaserplatten 2-lagig (BSK) | WUN-H2-E00-F06 | CEILING | D1 0.001 m | 1115Dfl0000028558/04 | m² | Maler- und Lackierarbeiten | 4 | 0.001 | 0 | 1 | Bekleidung | D1 | 0 | 0 | NEW | 2.5 | AllplanAttributes - ash_lichte Raumhöhe: 2.500000
Handlauf | WUN-H2-E00-F08 | CLADDING | 97 0.001 m | 1115Sfl0000158621/02 | m² | Maler- und Lackierarbeiten | 2 | 0.001 | 0 | 1 | Seitenfläche | 97 | 0 | 0 | NEW | AllplanAttributes - Bezeichnung: Handlauf
Handlauf | WUN-H2-E00-F08 | CLADDING | 97 0.001 m | 1115Sfl0000158798/02 | m² | Maler- und Lackierarbeiten | 2 | 0.001 | 0 | 1 | Seitenfläche | 97 | 0 | 0 | NEW | AllplanAttributes - Bezeichnung: Handlauf
Acrobyn | WUN-H2-E00-F08 | CLADDING | 84 0.001 m | 1115Sfl0000159683/02 | m² | Maler- und Lackierarbeiten | 2 | 0.001 | 0 | 1 | Seitenfläche | 84 | 0 | 0 | NEW | AllplanAttributes - Bezeichnung: Acrobyn
PVC Bahnenware Holzoptik | WUN-H2-E00-F08 | FLOORING | Ku1 0.2 m | 1115Bfl0000005022/01 | m² | Bodenbelagsarbeiten | 1 | 0.2 | 0 | 1 | Bodenfläche | Ku1 | 0 | 0 | NEW | AllplanAttributes - Bezeichnung: PVC Bahnenware Holzoptik; Raumnr. Bauherr: 2.11_A2_02; ash B_Aufbau: B1; ash B_Rutschhemmung: R9
Gipsfaserplatten 2-lagig (BSK) | WUN-H2-E00-F08 | CEILING | layer 0.036 m | 1115Dfl0000027035/01 | m² | Trockenbauarbeiten | 1 | 0.036 | 0 | 1 | Deckenfläche |  | 0 | 0 | NEW | 2.5 | AllplanAttributes - Bezeichnung: Gipsfaserplatten 2-lagig (BSK)
Gipsfaserplatten 2-lagig (BSK) | WUN-H2-E00-F08 | CEILING | Installationshöhe 0.664 m | 1115Dfl0000027035/02 | m² | Trockenbauarbeiten | 2 | 0.664 | 0 | 1 | Bekleidung | Installationshöhe | 0 | 0 | NEW | 2.5 | Pset_CoveringCommon - FireRating: für korrekte FläVisu; AllplanAttributes - ash_lichte Raumhöhe: 2.500000
Gipsfaserplatten 2-lagig (BSK) | WUN-H2-E00-F08 | CEILING | A1 0.2 m | 1115Dfl0000027035/03 | m² | Trockenbauarbeiten | 3 | 0.2 | 0 | 1 | Bekleidung | A1 | 0 | 0 | NEW | 2.5 | Pset_CoveringCommon - FireRating: F30; AcousticRating: -; AllplanAttributes - ash_lichte Raumhöhe: 2.500000
Gipsfaserplatten 2-lagig (BSK) | WUN-H2-E00-F08 | CEILING | D1 0.001 m | 1115Dfl0000027035/04 | m² | Maler- und Lackierarbeiten | 4 | 0.001 | 0 | 1 | Bekleidung | D1 | 0 | 0 | NEW | 2.5 | AllplanAttributes - ash_lichte Raumhöhe: 2.500000
Gipsfaserplatten 2-lagig (BSK) | WUN-H2-E00-F08 | CEILING | layer 0.036 m | 1115Dfl0000100410/01 | m² | Trockenbauarbeiten | 1 | 0.036 | 0 | 1 | Deckenfläche |  | 0 | 0 | NEW | 2.5 | AllplanAttributes - Bezeichnung: Gipsfaserplatten 2-lagig (BSK)
Gipsfaserplatten 2-lagig (BSK) | WUN-H2-E00-F08 | CEILING | Installationshöhe 0.664 m | 1115Dfl0000100410/02 | m² | Trockenbauarbeiten | 2 | 0.664 | 0 | 1 | Bekleidung | Installationshöhe | 0 | 0 | NEW | 2.5 | Pset_CoveringCommon - FireRating: für korrekte FläVisu; AllplanAttributes - ash_lichte Raumhöhe: 2.500000
Gipsfaserplatten 2-lagig (BSK) | WUN-H2-E00-F08 | CEILING | Aa 0.2 m | 1115Dfl0000100410/03 | m² | Trockenbauarbeiten | 3 | 0.2 | 0 | 1 | Bekleidung | Aa | 0 | 0 | NEW | 2.5 | Pset_CoveringCommon - FireRating: F30; AcousticRating: -; AllplanAttributes - ash_lichte Raumhöhe: 2.500000
Gipsfaserplatten 2-lagig (BSK) | WUN-H2-E00-F08 | CEILING | D1 0.001 m | 1115Dfl0000100410/04 | m² | Maler- und Lackierarbeiten | 4 | 0.001 | 0 | 1 | Bekleidung | D1 | 0 | 0 | NEW | 2.5 | AllplanAttributes - ash_lichte Raumhöhe: 2.500000
 | WUN-H2-E00-T04 | FLOORING | Fl12 0.06 m | 1115Bfl0000118342/01 | m² | Bodenbelagsarbeiten | 1 | 0.06 | 0 | 1 | Bodenfläche | Fl12 | 0 | 0 | NEW | AllplanAttributes - Raumnr. Bauherr: 2.11_A2_02; ash B_Aufbau: B6; ash B_Rutschhemmung: R10
Fliesen Großformat | WUN-H2-E00-T04 | FLOORING | Fl12 0.2 m | 1115Bfl0000117792/01 | m² | Bodenbelagsarbeiten | 1 | 0.2 | 0 | 1 | Bodenfläche | Fl12 | 0 | 0 | NEW | AllplanAttributes - Bezeichnung: Fliesen Großformat; Raumnr. Bauherr: 2.11_A2_02; ash B_Aufbau: B4; ash B_Rutschhemmung: R10
Sichtbetonklasse SB3 | WUN-H2-E00-T04 | CLADDING | 03 0.001 m | 1115Sfl0813978675/02 | m² | Putz- und Stuckarbeiten | 2 | 0.001 | 0 | 1 | Seitenfläche | 03 | 0 | 0 | NEW | AllplanAttributes - Bezeichnung: Sichtbetonklasse SB3
Gipsfaserplatten 2-lagig (BSK) | WUN-H2-E00-T04 | CEILING | layer 0.036 m | 1115Dfl0000029548/01 | m² | Trockenbauarbeiten | 1 | 0.036 | 0 | 1 | Deckenfläche |  | 0 | 0 | NEW | 3.1 | AllplanAttributes - Bezeichnung: Gipsfaserplatten 2-lagig (BSK)
Gipsfaserplatten 2-lagig (BSK) | WUN-H2-E00-T04 | CEILING | Installationshöhe 0.164 m | 1115Dfl0000029548/02 | m² | Trockenbauarbeiten | 2 | 0.164 | 0 | 1 | Bekleidung | Installationshöhe | 0 | 0 | NEW | 3.1 | Pset_CoveringCommon - FireRating: für korrekte FläVisu; AllplanAttributes - ash_lichte Raumhöhe: 3.100000
Gipsfaserplatten 2-lagig (BSK) | WUN-H2-E00-T04 | CEILING | A1 0.1 m | 1115Dfl0000029548/03 | m² | Trockenbauarbeiten | 3 | 0.1 | 0 | 1 | Bekleidung | A1 | 0 | 0 | NEW | 3.1 | Pset_CoveringCommon - FireRating: F60; AcousticRating: -; AllplanAttributes - ash_lichte Raumhöhe: 3.100000
Gipsfaserplatten 2-lagig (BSK) | WUN-H2-E00-T04 | CEILING | D1 0.001 m | 1115Dfl0000029548/04 | m² | Maler- und Lackierarbeiten | 4 | 0.001 | 0 | 1 | Bekleidung | D1 | 0 | 0 | NEW | 3.1 | AllplanAttributes - ash_lichte Raumhöhe: 3.100000
 | WUN-H2-E00-T03 | FLOORING | Fl12 0.06 m | 1115Bfl0000118700/01 | m² | Bodenbelagsarbeiten | 1 | 0.06 | 0 | 1 | Bodenfläche | Fl12 | 0 | 0 | NEW | AllplanAttributes - Raumnr. Bauherr: 2.11_A2_02; ash B_Aufbau: B6; ash B_Rutschhemmung: R10
Fliesen Großformat | WUN-H2-E00-T03 | FLOORING | Fl12 0.2 m | 1115Bfl0000117416/01 | m² | Bodenbelagsarbeiten | 1 | 0.2 | 0 | 1 | Bodenfläche | Fl12 | 0 | 0 | NEW | AllplanAttributes - Bezeichnung: Fliesen Großformat; Raumnr. Bauherr: 2.11_A2_02; ash B_Aufbau: B4; ash B_Rutschhemmung: R10
Sichtbetonklasse SB3 | WUN-H2-E00-T03 | CLADDING | 03 0.001 m | 1115Sfl0813978676/02 | m² | Putz- und Stuckarbeiten | 2 | 0.001 | 0 | 1 | Seitenfläche | 03 | 0 | 0 | NEW | AllplanAttributes - Bezeichnung: Sichtbetonklasse SB3
Gipsfaserplatten 2-lagig (BSK) | WUN-H2-E00-T03 | CEILING | layer 0.036 m | 1115Dfl0000029543/01 | m² | Trockenbauarbeiten | 1 | 0.036 | 0 | 1 | Deckenfläche |  | 0 | 0 | NEW | 3.1 | AllplanAttributes - Bezeichnung: Gipsfaserplatten 2-lagig (BSK)
Gipsfaserplatten 2-lagig (BSK) | WUN-H2-E00-T03 | CEILING | Installationshöhe 0.164 m | 1115Dfl0000029543/02 | m² | Trockenbauarbeiten | 2 | 0.164 | 0 | 1 | Bekleidung | Installationshöhe | 0 | 0 | NEW | 3.1 | Pset_CoveringCommon - FireRating: für korrekte FläVisu; AllplanAttributes - ash_lichte Raumhöhe: 3.100000
Gipsfaserplatten 2-lagig (BSK) | WUN-H2-E00-T03 | CEILING | A1 0.1 m | 1115Dfl0000029543/03 | m² | Trockenbauarbeiten | 3 | 0.1 | 0 | 1 | Bekleidung | A1 | 0 | 0 | NEW | 3.1 | Pset_CoveringCommon - FireRating: F60; AcousticRating: -; AllplanAttributes - ash_lichte Raumhöhe: 3.100000
Gipsfaserplatten 2-lagig (BSK) | WUN-H2-E00-T03 | CEILING | D1 0.001 m | 1115Dfl0000029543/04 | m² | Maler- und Lackierarbeiten | 4 | 0.001 | 0 | 1 | Bekleidung | D1 | 0 | 0 | NEW | 3.1 | AllplanAttributes - ash_lichte Raumhöhe: 3.100000
PVC Bahnenware Holzoptik | WUN-H2-E00-F01 | FLOORING | Ku1 0.2 m | 1115Bfl0000005150/01 | m² | Bodenbelagsarbeiten | 1 | 0.2 | 0 | 1 | Bodenfläche | Ku1 | 0 | 0 | NEW | AllplanAttributes - Bezeichnung: PVC Bahnenware Holzoptik; Raumnr. Bauherr: 2.11_A2_02; ash B_Aufbau: B1; ash B_Rutschhemmung: R9
Gipsfaserplatten 2-lagig (BSK) | WUN-H2-E00-F01 | CEILING | layer 0.036 m | 1115Dfl0000005149/01 | m² | Trockenbauarbeiten | 1 | 0.036 | 0 | 1 | Deckenfläche |  | 0 | 0 | NEW | 2.75 | AllplanAttributes - Bezeichnung: Gipsfaserplatten 2-lagig (BSK)
Gipsfaserplatten 2-lagig (BSK) | WUN-H2-E00-F01 | CEILING | Installationshöhe 0.514 m | 1115Dfl0000005149/02 | m² | Trockenbauarbeiten | 2 | 0.514 | 0 | 1 | Bekleidung | Installationshöhe | 0 | 0 | NEW | 2.75 | Pset_CoveringCommon - FireRating: für korrekte FläVisu; AllplanAttributes - ash_lichte Raumhöhe: 2.750000
Gipsfaserplatten 2-lagig (BSK) | WUN-H2-E00-F01 | CEILING | A1 0.1 m | 1115Dfl0000005149/03 | m² | Trockenbauarbeiten | 3 | 0.1 | 0 | 1 | Bekleidung | A1 | 0 | 0 | NEW | 2.75 | Pset_CoveringCommon - FireRating: F30; AcousticRating: -; AllplanAttributes - ash_lichte Raumhöhe: 2.750000
Gipsfaserplatten 2-lagig (BSK) | WUN-H2-E00-F01 | CEILING | D1 0.001 m | 1115Dfl0000005149/04 | m² | Maler- und Lackierarbeiten | 4 | 0.001 | 0 | 1 | Bekleidung | D1 | 0 | 0 | NEW | 2.75 | AllplanAttributes - ash_lichte Raumhöhe: 2.750000
 | WUN-H2-E00-T02 | FLOORING | Fl12 0.06 m | 1115Bfl0000119052/01 | m² | Bodenbelagsarbeiten | 1 | 0.06 | 0 | 1 | Bodenfläche | Fl12 | 0 | 0 | NEW | AllplanAttributes - Raumnr. Bauherr: 2.11_A2_02; ash B_Aufbau: B6; ash B_Rutschhemmung: R10
Fliesen Großformat | WUN-H2-E00-T02 | FLOORING | Fl12 0.1 m | 1115Bfl0000119769/01 | m² | Bodenbelagsarbeiten | 1 | 0.1 | 0 | 1 | Bodenfläche | Fl12 | 0 | 0 | NEW | AllplanAttributes - Bezeichnung: Fliesen Großformat; Raumnr. Bauherr: 2.11_A2_02; ash B_Aufbau: B7; ash B_Rutschhemmung: R10
Fliesen Großformat | WUN-H2-E00-T02 | FLOORING | Fl12 0.2 m | 1115Bfl0000119406/01 | m² | Bodenbelagsarbeiten | 1 | 0.2 | 0 | 1 | Bodenfläche | Fl12 | 0 | 0 | NEW | AllplanAttributes - Bezeichnung: Fliesen Großformat; Raumnr. Bauherr: 2.11_A2_02; ash B_Aufbau: B4; ash B_Rutschhemmung: R10
Sichtbetonklasse SB3 | WUN-H2-E00-T02 | CLADDING | 03 0.001 m | 1115Sfl0813978677/02 | m² | Putz- und Stuckarbeiten | 2 | 0.001 | 0 | 1 | Seitenfläche | 03 | 0 | 0 | NEW | AllplanAttributes - Bezeichnung: Sichtbetonklasse SB3
Gipsfaserplatten 2-lagig (BSK) | WUN-H2-E00-T02 | CEILING | layer 0.036 m | 1115Dfl0000052024/01 | m² | Trockenbauarbeiten | 1 | 0.036 | 0 | 1 | Deckenfläche |  | 0 | 0 | NEW | 3.1 | AllplanAttributes - Bezeichnung: Gipsfaserplatten 2-lagig (BSK)
Gipsfaserplatten 2-lagig (BSK) | WUN-H2-E00-T02 | CEILING | Installationshöhe 0.164 m | 1115Dfl0000052024/02 | m² | Trockenbauarbeiten | 2 | 0.164 | 0 | 1 | Bekleidung | Installationshöhe | 0 | 0 | NEW | 3.1 | Pset_CoveringCommon - FireRating: für korrekte FläVisu; AllplanAttributes - ash_lichte Raumhöhe: 3.100000
Gipsfaserplatten 2-lagig (BSK) | WUN-H2-E00-T02 | CEILING | A1 0.1 m | 1115Dfl0000052024/03 | m² | Trockenbauarbeiten | 3 | 0.1 | 0 | 1 | Bekleidung | A1 | 0 | 0 | NEW | 3.1 | Pset_CoveringCommon - FireRating: F60; AcousticRating: -; AllplanAttributes - ash_lichte Raumhöhe: 3.100000
Gipsfaserplatten 2-lagig (BSK) | WUN-H2-E00-T02 | CEILING | D1 0.001 m | 1115Dfl0000052024/04 | m² | Maler- und Lackierarbeiten | 4 | 0.001 | 0 | 1 | Bekleidung | D1 | 0 | 0 | NEW | 3.1 | AllplanAttributes - ash_lichte Raumhöhe: 3.100000
PVC Bahnenware Holzoptik | WUN-H2-E00-F02 | FLOORING | Ku1 0.2 m | 1115Bfl0000005153/01 | m² | Bodenbelagsarbeiten | 1 | 0.2 | 0 | 1 | Bodenfläche | Ku1 | 0 | 0 | NEW | AllplanAttributes - Bezeichnung: PVC Bahnenware Holzoptik; Raumnr. Bauherr: 2.11_A2_02; ash B_Aufbau: B1; ash B_Rutschhemmung: R9
Acrobyn | WUN-H2-E00-F02 | CLADDING | 84 0.001 m | 1115Sfl0000082156/02 | m² | Maler- und Lackierarbeiten | 2 | 0.001 | 0 | 1 | Seitenfläche | 84 | 0 | 0 | NEW | AllplanAttributes - Bezeichnung: Acrobyn
Gipsfaserplatten 2-lagig (BSK) | WUN-H2-E00-F02 | CEILING | layer 0.036 m | 1115Dfl0000005154/01 | m² | Trockenbauarbeiten | 1 | 0.036 | 0 | 1 | Deckenfläche |  | 0 | 0 | NEW | 2.65 | AllplanAttributes - Bezeichnung: Gipsfaserplatten 2-lagig (BSK)
Gipsfaserplatten 2-lagig (BSK) | WUN-H2-E00-F02 | CEILING | Installationshöhe 0.614 m | 1115Dfl0000005154/02 | m² | Trockenbauarbeiten | 2 | 0.614 | 0 | 1 | Bekleidung | Installationshöhe | 0 | 0 | NEW | 2.65 | Pset_CoveringCommon - FireRating: für korrekte FläVisu; AllplanAttributes - ash_lichte Raumhöhe: 2.650000
Gipsfaserplatten 2-lagig (BSK) | WUN-H2-E00-F02 | CEILING | A1 0.1 m | 1115Dfl0000005154/03 | m² | Trockenbauarbeiten | 3 | 0.1 | 0 | 1 | Bekleidung | A1 | 0 | 0 | NEW | 2.65 | Pset_CoveringCommon - FireRating: F60; AcousticRating: -; AllplanAttributes - ash_lichte Raumhöhe: 2.650000
Gipsfaserplatten 2-lagig (BSK) | WUN-H2-E00-F02 | CEILING | D1 0.001 m | 1115Dfl0000005154/04 | m² | Maler- und Lackierarbeiten | 4 | 0.001 | 0 | 1 | Bekleidung | D1 | 0 | 0 | NEW | 2.65 | AllplanAttributes - ash_lichte Raumhöhe: 2.650000
Acrobyn | WUN-H2-E00-F03 | CLADDING | 84 0.001 m | 1115Sfl0000159329/02 | m² | Maler- und Lackierarbeiten | 2 | 0.001 | 0 | 1 | Seitenfläche | 84 | 0 | 0 | NEW | AllplanAttributes - Bezeichnung: Acrobyn
Acrobyn | WUN-H2-E00-F03 | CLADDING | 84 0.001 m | 1115Sfl0000159506/02 | m² | Maler- und Lackierarbeiten | 2 | 0.001 | 0 | 1 | Seitenfläche | 84 | 0 | 0 | NEW | AllplanAttributes - Bezeichnung: Acrobyn
Acrobyn | WUN-H2-E00-F03 | CLADDING | 84 0.001 m | 1115Sfl0000159861/02 | m² | Maler- und Lackierarbeiten | 2 | 0.001 | 0 | 1 | Seitenfläche | 84 | 0 | 0 | NEW | AllplanAttributes - Bezeichnung: Acrobyn
Handlauf | WUN-H2-E00-F03 | CLADDING | 97 0.001 m | 1115Sfl0000158975/02 | m² | Maler- und Lackierarbeiten | 2 | 0.001 | 0 | 1 | Seitenfläche | 97 | 0 | 0 | NEW | AllplanAttributes - Bezeichnung: Handlauf
Handlauf | WUN-H2-E00-F03 | CLADDING | 97 0.001 m | 1115Sfl0000157544/02 | m² | Maler- und Lackierarbeiten | 2 | 0.001 | 0 | 1 | Seitenfläche | 97 | 0 | 0 | NEW | AllplanAttributes - Bezeichnung: Handlauf
PVC Bahnenware Holzoptik | WUN-H2-E00-F03 | FLOORING | Ku1 0.2 m | 1115Bfl0000005176/01 | m² | Bodenbelagsarbeiten | 1 | 0.2 | 0 | 1 | Bodenfläche | Ku1 | 0 | 0 | NEW | AllplanAttributes - Bezeichnung: PVC Bahnenware Holzoptik; Raumnr. Bauherr: 2.11_A2_02; ash B_Aufbau: B1; ash B_Rutschhemmung: R9
Gipsfaserplatten 2-lagig (BSK) | WUN-H2-E00-F03 | CEILING | layer 0.036 m | 1115Dfl0000097390/01 | m² | Trockenbauarbeiten | 1 | 0.036 | 0 | 1 | Deckenfläche |  | 0 | 0 | NEW | 2.5 | AllplanAttributes - Bezeichnung: Gipsfaserplatten 2-lagig (BSK)
Gipsfaserplatten 2-lagig (BSK) | WUN-H2-E00-F03 | CEILING | Installationshöhe 0.714 m | 1115Dfl0000097390/02 | m² | Trockenbauarbeiten | 2 | 0.714 | 0 | 1 | Bekleidung | Installationshöhe | 0 | 0 | NEW | 2.5 | Pset_CoveringCommon - FireRating: für korrekte FläVisu; AllplanAttributes - ash_lichte Raumhöhe: 2.500000
Gipsfaserplatten 2-lagig (BSK) | WUN-H2-E00-F03 | CEILING | Aa 0.15 m | 1115Dfl0000097390/03 | m² | Trockenbauarbeiten | 3 | 0.15 | 0 | 1 | Bekleidung | Aa | 0 | 0 | NEW | 2.5 | AllplanAttributes - ash_lichte Raumhöhe: 2.500000; Pset_CoveringCommon - AcousticRating: -
Gipsfaserplatten 2-lagig (BSK) | WUN-H2-E00-F03 | CEILING | D1 0.001 m | 1115Dfl0000097390/04 | m² | Maler- und Lackierarbeiten | 4 | 0.001 | 0 | 1 | Bekleidung | D1 | 0 | 0 | NEW | 2.5 | AllplanAttributes - ash_lichte Raumhöhe: 2.500000
Gipsfaserplatten 2-lagig (BSK) | WUN-H2-E00-F03 | CEILING | layer 0.036 m | 1115Dfl0813977669/01 | m² | Trockenbauarbeiten | 1 | 0.036 | 0 | 1 | Deckenfläche |  | 0 | 0 | NEW | 2.5 | AllplanAttributes - Bezeichnung: Gipsfaserplatten 2-lagig (BSK)
Gipsfaserplatten 2-lagig (BSK) | WUN-H2-E00-F03 | CEILING | Installationshöhe 0.714 m | 1115Dfl0813977669/02 | m² | Trockenbauarbeiten | 2 | 0.714 | 0 | 1 | Bekleidung | Installationshöhe | 0 | 0 | NEW | 2.5 | Pset_CoveringCommon - FireRating: für korrekte FläVisu; AllplanAttributes - ash_lichte Raumhöhe: 2.500000
Gipsfaserplatten 2-lagig (BSK) | WUN-H2-E00-F03 | CEILING | A1 0.15 m | 1115Dfl0813977669/03 | m² | Trockenbauarbeiten | 3 | 0.15 | 0 | 1 | Bekleidung | A1 | 0 | 0 | NEW | 2.5 | AllplanAttributes - ash_lichte Raumhöhe: 2.500000; Pset_CoveringCommon - AcousticRating: -
Gipsfaserplatten 2-lagig (BSK) | WUN-H2-E00-F03 | CEILING | D1 0.001 m | 1115Dfl0813977669/04 | m² | Maler- und Lackierarbeiten | 4 | 0.001 | 0 | 1 | Bekleidung | D1 | 0 | 0 | NEW | 2.5 | AllplanAttributes - ash_lichte Raumhöhe: 2.500000
Gipsfaserplatten 2-lagig (BSK) | WUN-H2-E00-F03 | CEILING | layer 0.036 m | 1115Dfl0813979984/01 | m² | Trockenbauarbeiten | 1 | 0.036 | 0 | 1 | Deckenfläche |  | 0 | 0 | NEW | 3.1 | AllplanAttributes - Bezeichnung: Gipsfaserplatten 2-lagig (BSK)
Gipsfaserplatten 2-lagig (BSK) | WUN-H2-E00-F03 | CEILING | Installationshöhe 0.164 m | 1115Dfl0813979984/02 | m² | Trockenbauarbeiten | 2 | 0.164 | 0 | 1 | Bekleidung | Installationshöhe | 0 | 0 | NEW | 3.1 | Pset_CoveringCommon - FireRating: -; AcousticRating: -; AllplanAttributes - ash_lichte Raumhöhe: 3.100000
Gipsfaserplatten 2-lagig (BSK) | WUN-H2-E00-F03 | CEILING | A1 0.1 m | 1115Dfl0813979984/03 | m² | Trockenbauarbeiten | 3 | 0.1 | 0 | 1 | Bekleidung | A1 | 0 | 0 | NEW | 3.1 | Pset_CoveringCommon - FireRating: -; AcousticRating: -; AllplanAttributes - ash_lichte Raumhöhe: 3.100000
Gipsfaserplatten 2-lagig (BSK) | WUN-H2-E00-F03 | CEILING | D1 0.001 m | 1115Dfl0813979984/04 | m² | Maler- und Lackierarbeiten | 4 | 0.001 | 0 | 1 | Bekleidung | D1 | 0 | 0 | NEW | 3.1 | AllplanAttributes - ash_lichte Raumhöhe: 3.100000
Gipsfaserplatten 2-lagig (BSK) | WUN-H2-E00-F03 | CEILING | layer 0.036 m | 1115Dfl0813979915/01 | m² | Trockenbauarbeiten | 1 | 0.036 | 0 | 1 | Deckenfläche |  | 0 | 0 | NEW | 3.1 | AllplanAttributes - Bezeichnung: Gipsfaserplatten 2-lagig (BSK)
Gipsfaserplatten 2-lagig (BSK) | WUN-H2-E00-F03 | CEILING | Installationshöhe 0.164 m | 1115Dfl0813979915/02 | m² | Trockenbauarbeiten | 2 | 0.164 | 0 | 1 | Bekleidung | Installationshöhe | 0 | 0 | NEW | 3.1 | Pset_CoveringCommon - FireRating: -; AcousticRating: -; AllplanAttributes - ash_lichte Raumhöhe: 3.100000
Gipsfaserplatten 2-lagig (BSK) | WUN-H2-E00-F03 | CEILING | A1 0.1 m | 1115Dfl0813979915/03 | m² | Trockenbauarbeiten | 3 | 0.1 | 0 | 1 | Bekleidung | A1 | 0 | 0 | NEW | 3.1 | Pset_CoveringCommon - FireRating: -; AcousticRating: -; AllplanAttributes - ash_lichte Raumhöhe: 3.100000
Gipsfaserplatten 2-lagig (BSK) | WUN-H2-E00-F03 | CEILING | D1 0.001 m | 1115Dfl0813979915/04 | m² | Maler- und Lackierarbeiten | 4 | 0.001 | 0 | 1 | Bekleidung | D1 | 0 | 0 | NEW | 3.1 | AllplanAttributes - ash_lichte Raumhöhe: 3.100000
Handlauf | WUN-H2-E00-F07 | CLADDING | 97 0.001 m | 1115Sfl0000090048/02 | m² | Maler- und Lackierarbeiten | 2 | 0.001 | 0 | 1 | Seitenfläche | 97 | 0 | 0 | NEW | AllplanAttributes - Bezeichnung: Handlauf
Handlauf | WUN-H2-E00-F07 | CLADDING | 97 0.001 m | 1115Sfl0000158444/02 | m² | Maler- und Lackierarbeiten | 2 | 0.001 | 0 | 1 | Seitenfläche | 97 | 0 | 0 | NEW | AllplanAttributes - Bezeichnung: Handlauf
Handlauf | WUN-H2-E00-F07 | CLADDING | 97 0.001 m | 1115Sfl0000089757/02 | m² | Maler- und Lackierarbeiten | 2 | 0.001 | 0 | 1 | Seitenfläche | 97 | 0 | 0 | NEW | AllplanAttributes - Bezeichnung: Handlauf
PVC Bahnenware Holzoptik | WUN-H2-E00-F07 | FLOORING | Ku1 0.2 m | 1115Bfl0000005215/01 | m² | Bodenbelagsarbeiten | 1 | 0.2 | 0 | 1 | Bodenfläche | Ku1 | 0 | 0 | NEW | AllplanAttributes - Bezeichnung: PVC Bahnenware Holzoptik; Raumnr. Bauherr: 2.11_A2_02; ash B_Aufbau: B1; ash B_Rutschhemmung: R9
Gipsfaserplatten 2-lagig (BSK) | WUN-H2-E00-F07 | CEILING | layer 0.036 m | 1115Dfl0000099779/01 | m² | Trockenbauarbeiten | 1 | 0.036 | 0 | 1 | Deckenfläche |  | 0 | 0 | NEW | 2.5 | AllplanAttributes - Bezeichnung: Gipsfaserplatten 2-lagig (BSK)
Gipsfaserplatten 2-lagig (BSK) | WUN-H2-E00-F07 | CEILING | Installationshöhe 0.714 m | 1115Dfl0000099779/02 | m² | Trockenbauarbeiten | 2 | 0.714 | 0 | 1 | Bekleidung | Installationshöhe | 0 | 0 | NEW | 2.5 | Pset_CoveringCommon - FireRating: für korrekte FläVisu; AllplanAttributes - ash_lichte Raumhöhe: 2.500000
Gipsfaserplatten 2-lagig (BSK) | WUN-H2-E00-F07 | CEILING | Aa 0.15 m | 1115Dfl0000099779/03 | m² | Trockenbauarbeiten | 3 | 0.15 | 0 | 1 | Bekleidung | Aa | 0 | 0 | NEW | 2.5 | AllplanAttributes - ash_lichte Raumhöhe: 2.500000; Pset_CoveringCommon - AcousticRating: -
Gipsfaserplatten 2-lagig (BSK) | WUN-H2-E00-F07 | CEILING | D1 0.001 m | 1115Dfl0000099779/04 | m² | Maler- und Lackierarbeiten | 4 | 0.001 | 0 | 1 | Bekleidung | D1 | 0 | 0 | NEW | 2.5 | AllplanAttributes - ash_lichte Raumhöhe: 2.500000
Gipsfaserplatten 2-lagig (BSK) | WUN-H2-E00-F07 | CEILING | layer 0.036 m | 1115Dfl0000047615/01 | m² | Trockenbauarbeiten | 1 | 0.036 | 0 | 1 | Deckenfläche |  | 0 | 0 | NEW | 2.5 | AllplanAttributes - Bezeichnung: Gipsfaserplatten 2-lagig (BSK)
Gipsfaserplatten 2-lagig (BSK) | WUN-H2-E00-F07 | CEILING | Installationshöhe 0.714 m | 1115Dfl0000047615/02 | m² | Trockenbauarbeiten | 2 | 0.714 | 0 | 1 | Bekleidung | Installationshöhe | 0 | 0 | NEW | 2.5 | Pset_CoveringCommon - FireRating: für korrekte FläVisu; AllplanAttributes - ash_lichte Raumhöhe: 2.500000
Gipsfaserplatten 2-lagig (BSK) | WUN-H2-E00-F07 | CEILING | A1 0.15 m | 1115Dfl0000047615/03 | m² | Trockenbauarbeiten | 3 | 0.15 | 0 | 1 | Bekleidung | A1 | 0 | 0 | NEW | 2.5 | AllplanAttributes - ash_lichte Raumhöhe: 2.500000; Pset_CoveringCommon - AcousticRating: -
Gipsfaserplatten 2-lagig (BSK) | WUN-H2-E00-F07 | CEILING | D1 0.001 m | 1115Dfl0000047615/04 | m² | Maler- und Lackierarbeiten | 4 | 0.001 | 0 | 1 | Bekleidung | D1 | 0 | 0 | NEW | 2.5 | AllplanAttributes - ash_lichte Raumhöhe: 2.500000
Gipsfaserplatten 2-lagig (BSK) | WUN-H2-E00-F07 | CEILING | layer 0.036 m | 1115Dfl0813980927/01 | m² | Trockenbauarbeiten | 1 | 0.036 | 0 | 1 | Deckenfläche |  | 0 | 0 | NEW | 3.1 | AllplanAttributes - Bezeichnung: Gipsfaserplatten 2-lagig (BSK)
Gipsfaserplatten 2-lagig (BSK) | WUN-H2-E00-F07 | CEILING | Installationshöhe 0.164 m | 1115Dfl0813980927/02 | m² | Trockenbauarbeiten | 2 | 0.164 | 0 | 1 | Bekleidung | Installationshöhe | 0 | 0 | NEW | 3.1 | Pset_CoveringCommon - FireRating: -; AcousticRating: -; AllplanAttributes - ash_lichte Raumhöhe: 3.100000
Gipsfaserplatten 2-lagig (BSK) | WUN-H2-E00-F07 | CEILING | A1 0.1 m | 1115Dfl0813980927/03 | m² | Trockenbauarbeiten | 3 | 0.1 | 0 | 1 | Bekleidung | A1 | 0 | 0 | NEW | 3.1 | Pset_CoveringCommon - FireRating: -; AcousticRating: -; AllplanAttributes - ash_lichte Raumhöhe: 3.100000
Gipsfaserplatten 2-lagig (BSK) | WUN-H2-E00-F07 | CEILING | D1 0.001 m | 1115Dfl0813980927/04 | m² | Maler- und Lackierarbeiten | 4 | 0.001 | 0 | 1 | Bekleidung | D1 | 0 | 0 | NEW | 3.1 | AllplanAttributes - ash_lichte Raumhöhe: 3.100000
Gipsfaserplatten 2-lagig (BSK) | WUN-H2-E00-F07 | CEILING | layer 0.036 m | 1115Dfl0813981579/01 | m² | Trockenbauarbeiten | 1 | 0.036 | 0 | 1 | Deckenfläche |  | 0 | 0 | NEW | 3.1 | AllplanAttributes - Bezeichnung: Gipsfaserplatten 2-lagig (BSK)
Gipsfaserplatten 2-lagig (BSK) | WUN-H2-E00-F07 | CEILING | Installationshöhe 0.164 m | 1115Dfl0813981579/02 | m² | Trockenbauarbeiten | 2 | 0.164 | 0 | 1 | Bekleidung | Installationshöhe | 0 | 0 | NEW | 3.1 | Pset_CoveringCommon - FireRating: -; AcousticRating: -; AllplanAttributes - ash_lichte Raumhöhe: 3.100000
Gipsfaserplatten 2-lagig (BSK) | WUN-H2-E00-F07 | CEILING | A1 0.1 m | 1115Dfl0813981579/03 | m² | Trockenbauarbeiten | 3 | 0.1 | 0 | 1 | Bekleidung | A1 | 0 | 0 | NEW | 3.1 | Pset_CoveringCommon - FireRating: -; AcousticRating: -; AllplanAttributes - ash_lichte Raumhöhe: 3.100000
Gipsfaserplatten 2-lagig (BSK) | WUN-H2-E00-F07 | CEILING | D1 0.001 m | 1115Dfl0813981579/04 | m² | Maler- und Lackierarbeiten | 4 | 0.001 | 0 | 1 | Bekleidung | D1 | 0 | 0 | NEW | 3.1 | AllplanAttributes - ash_lichte Raumhöhe: 3.100000
Handlauf | WUN-H2-E00-F11 | CLADDING | 97 0.001 m | 1115Sfl0000092085/02 | m² | Maler- und Lackierarbeiten | 2 | 0.001 | 0 | 1 | Seitenfläche | 97 | 0 | 0 | NEW | AllplanAttributes - Bezeichnung: Handlauf
Handlauf | WUN-H2-E00-F11 | CLADDING | 97 0.001 m | 1115Sfl0000091503/02 | m² | Maler- und Lackierarbeiten | 2 | 0.001 | 0 | 1 | Seitenfläche | 97 | 0 | 0 | NEW | AllplanAttributes - Bezeichnung: Handlauf
Handlauf | WUN-H2-E00-F11 | CLADDING | 97 0.001 m | 1115Sfl0000091794/02 | m² | Maler- und Lackierarbeiten | 2 | 0.001 | 0 | 1 | Seitenfläche | 97 | 0 | 0 | NEW | AllplanAttributes - Bezeichnung: Handlauf
PVC Bahnenware Holzoptik | WUN-H2-E00-F11 | FLOORING | Ku1 0.2 m | 1115Bfl0000005195/01 | m² | Bodenbelagsarbeiten | 1 | 0.2 | 0 | 1 | Bodenfläche | Ku1 | 0 | 0 | NEW | AllplanAttributes - Bezeichnung: PVC Bahnenware Holzoptik; Raumnr. Bauherr: 2.11_A2_02; ash B_Aufbau: B1; ash B_Rutschhemmung: R9
Gipsfaserplatten 2-lagig (BSK) | WUN-H2-E00-F11 | CEILING | layer 0.036 m | 1115Dfl0000101637/01 | m² | Trockenbauarbeiten | 1 | 0.036 | 0 | 1 | Deckenfläche |  | 0 | 0 | NEW | 2.5 | AllplanAttributes - Bezeichnung: Gipsfaserplatten 2-lagig (BSK)
Gipsfaserplatten 2-lagig (BSK) | WUN-H2-E00-F11 | CEILING | Installationshöhe 0.714 m | 1115Dfl0000101637/02 | m² | Trockenbauarbeiten | 2 | 0.714 | 0 | 1 | Bekleidung | Installationshöhe | 0 | 0 | NEW | 2.5 | Pset_CoveringCommon - FireRating: für korrekte FläVisu; AllplanAttributes - ash_lichte Raumhöhe: 2.500000
Gipsfaserplatten 2-lagig (BSK) | WUN-H2-E00-F11 | CEILING | Aa 0.15 m | 1115Dfl0000101637/03 | m² | Trockenbauarbeiten | 3 | 0.15 | 0 | 1 | Bekleidung | Aa | 0 | 0 | NEW | 2.5 | AllplanAttributes - ash_lichte Raumhöhe: 2.500000; Pset_CoveringCommon - AcousticRating: -
Gipsfaserplatten 2-lagig (BSK) | WUN-H2-E00-F11 | CEILING | D1 0.001 m | 1115Dfl0000101637/04 | m² | Maler- und Lackierarbeiten | 4 | 0.001 | 0 | 1 | Bekleidung | D1 | 0 | 0 | NEW | 2.5 | AllplanAttributes - ash_lichte Raumhöhe: 2.500000
Gipsfaserplatten 2-lagig (BSK) | WUN-H2-E00-F11 | CEILING | layer 0.036 m | 1115Dfl0000027976/01 | m² | Trockenbauarbeiten | 1 | 0.036 | 0 | 1 | Deckenfläche |  | 0 | 0 | NEW | 2.5 | AllplanAttributes - Bezeichnung: Gipsfaserplatten 2-lagig (BSK)
Gipsfaserplatten 2-lagig (BSK) | WUN-H2-E00-F11 | CEILING | Installationshöhe 0.714 m | 1115Dfl0000027976/02 | m² | Trockenbauarbeiten | 2 | 0.714 | 0 | 1 | Bekleidung | Installationshöhe | 0 | 0 | NEW | 2.5 | Pset_CoveringCommon - FireRating: für korrekte FläVisu; AllplanAttributes - ash_lichte Raumhöhe: 2.500000
Gipsfaserplatten 2-lagig (BSK) | WUN-H2-E00-F11 | CEILING | A1 0.15 m | 1115Dfl0000027976/03 | m² | Trockenbauarbeiten | 3 | 0.15 | 0 | 1 | Bekleidung | A1 | 0 | 0 | NEW | 2.5 | AllplanAttributes - ash_lichte Raumhöhe: 2.500000; Pset_CoveringCommon - AcousticRating: -
Gipsfaserplatten 2-lagig (BSK) | WUN-H2-E00-F11 | CEILING | D1 0.001 m | 1115Dfl0000027976/04 | m² | Maler- und Lackierarbeiten | 4 | 0.001 | 0 | 1 | Bekleidung | D1 | 0 | 0 | NEW | 2.5 | AllplanAttributes - ash_lichte Raumhöhe: 2.500000
Gipsfaserplatten 2-lagig (BSK) | WUN-H2-E00-F11 | CEILING | layer 0.036 m | 1115Dfl0000005196/01 | m² | Trockenbauarbeiten | 1 | 0.036 | 0 | 1 | Deckenfläche |  | 0 | 0 | NEW | 3.1 | AllplanAttributes - Bezeichnung: Gipsfaserplatten 2-lagig (BSK)
Gipsfaserplatten 2-lagig (BSK) | WUN-H2-E00-F11 | CEILING | Installationshöhe 0.164 m | 1115Dfl0000005196/02 | m² | Trockenbauarbeiten | 2 | 0.164 | 0 | 1 | Bekleidung | Installationshöhe | 0 | 0 | NEW | 3.1 | Pset_CoveringCommon - FireRating: -; AcousticRating: -; AllplanAttributes - ash_lichte Raumhöhe: 3.100000
Gipsfaserplatten 2-lagig (BSK) | WUN-H2-E00-F11 | CEILING | A1 0.1 m | 1115Dfl0000005196/03 | m² | Trockenbauarbeiten | 3 | 0.1 | 0 | 1 | Bekleidung | A1 | 0 | 0 | NEW | 3.1 | Pset_CoveringCommon - FireRating: -; AcousticRating: -; AllplanAttributes - ash_lichte Raumhöhe: 3.100000
Gipsfaserplatten 2-lagig (BSK) | WUN-H2-E00-F11 | CEILING | D1 0.001 m | 1115Dfl0000005196/04 | m² | Maler- und Lackierarbeiten | 4 | 0.001 | 0 | 1 | Bekleidung | D1 | 0 | 0 | NEW | 3.1 | AllplanAttributes - ash_lichte Raumhöhe: 3.100000
Handlauf | WUN-H2-E00-F09 | CLADDING | 97 0.001 m | 1115Sfl0000090630/02 | m² | Maler- und Lackierarbeiten | 2 | 0.001 | 0 | 1 | Seitenfläche | 97 | 0 | 0 | NEW | AllplanAttributes - Bezeichnung: Handlauf
Handlauf | WUN-H2-E00-F09 | CLADDING | 97 0.001 m | 1115Sfl0000091212/02 | m² | Maler- und Lackierarbeiten | 2 | 0.001 | 0 | 1 | Seitenfläche | 97 | 0 | 0 | NEW | AllplanAttributes - Bezeichnung: Handlauf
Handlauf | WUN-H2-E00-F09 | CLADDING | 97 0.001 m | 1115Sfl0000158083/02 | m² | Maler- und Lackierarbeiten | 2 | 0.001 | 0 | 1 | Seitenfläche | 97 | 0 | 0 | NEW | AllplanAttributes - Bezeichnung: Handlauf
Handlauf | WUN-H2-E00-F09 | CLADDING | 97 0.001 m | 1115Sfl0000158260/02 | m² | Maler- und Lackierarbeiten | 2 | 0.001 | 0 | 1 | Seitenfläche | 97 | 0 | 0 | NEW | AllplanAttributes - Bezeichnung: Handlauf
PVC Bahnenware Holzoptik | WUN-H2-E00-F09 | FLOORING | Ku1 0.2 m | 1115Bfl0000005209/01 | m² | Bodenbelagsarbeiten | 1 | 0.2 | 0 | 1 | Bodenfläche | Ku1 | 0 | 0 | NEW | AllplanAttributes - Bezeichnung: PVC Bahnenware Holzoptik; Raumnr. Bauherr: 2.11_A2_02; ash B_Aufbau: B1; ash B_Rutschhemmung: R9
Gipsfaserplatten 2-lagig (BSK) | WUN-H2-E00-F09 | CEILING | layer 0.036 m | 1115Dfl0000101003/01 | m² | Trockenbauarbeiten | 1 | 0.036 | 0 | 1 | Deckenfläche |  | 0 | 0 | NEW | 2.5 | AllplanAttributes - Bezeichnung: Gipsfaserplatten 2-lagig (BSK)
Gipsfaserplatten 2-lagig (BSK) | WUN-H2-E00-F09 | CEILING | Installationshöhe 0.714 m | 1115Dfl0000101003/02 | m² | Trockenbauarbeiten | 2 | 0.714 | 0 | 1 | Bekleidung | Installationshöhe | 0 | 0 | NEW | 2.5 | Pset_CoveringCommon - FireRating: für korrekte FläVisu; AllplanAttributes - ash_lichte Raumhöhe: 2.500000
Gipsfaserplatten 2-lagig (BSK) | WUN-H2-E00-F09 | CEILING | Aa 0.15 m | 1115Dfl0000101003/03 | m² | Trockenbauarbeiten | 3 | 0.15 | 0 | 1 | Bekleidung | Aa | 0 | 0 | NEW | 2.5 | AllplanAttributes - ash_lichte Raumhöhe: 2.500000; Pset_CoveringCommon - AcousticRating: -
Gipsfaserplatten 2-lagig (BSK) | WUN-H2-E00-F09 | CEILING | D1 0.001 m | 1115Dfl0000101003/04 | m² | Maler- und Lackierarbeiten | 4 | 0.001 | 0 | 1 | Bekleidung | D1 | 0 | 0 | NEW | 2.5 | AllplanAttributes - ash_lichte Raumhöhe: 2.500000
Gipsfaserplatten 2-lagig (BSK) | WUN-H2-E00-F09 | CEILING | layer 0.036 m | 1115Dfl0000028267/01 | m² | Trockenbauarbeiten | 1 | 0.036 | 0 | 1 | Deckenfläche |  | 0 | 0 | NEW | 2.5 | AllplanAttributes - Bezeichnung: Gipsfaserplatten 2-lagig (BSK)
Gipsfaserplatten 2-lagig (BSK) | WUN-H2-E00-F09 | CEILING | Installationshöhe 0.714 m | 1115Dfl0000028267/02 | m² | Trockenbauarbeiten | 2 | 0.714 | 0 | 1 | Bekleidung | Installationshöhe | 0 | 0 | NEW | 2.5 | Pset_CoveringCommon - FireRating: für korrekte FläVisu; AllplanAttributes - ash_lichte Raumhöhe: 2.500000
Gipsfaserplatten 2-lagig (BSK) | WUN-H2-E00-F09 | CEILING | A1 0.15 m | 1115Dfl0000028267/03 | m² | Trockenbauarbeiten | 3 | 0.15 | 0 | 1 | Bekleidung | A1 | 0 | 0 | NEW | 2.5 | AllplanAttributes - ash_lichte Raumhöhe: 2.500000; Pset_CoveringCommon - AcousticRating: -
Gipsfaserplatten 2-lagig (BSK) | WUN-H2-E00-F09 | CEILING | D1 0.001 m | 1115Dfl0000028267/04 | m² | Maler- und Lackierarbeiten | 4 | 0.001 | 0 | 1 | Bekleidung | D1 | 0 | 0 | NEW | 2.5 | AllplanAttributes - ash_lichte Raumhöhe: 2.500000
Gipsfaserplatten 2-lagig (BSK) | WUN-H2-E00-F09 | CEILING | layer 0.036 m | 1115Dfl0000005210/01 | m² | Trockenbauarbeiten | 1 | 0.036 | 0 | 1 | Deckenfläche |  | 0 | 0 | NEW | 3.1 | AllplanAttributes - Bezeichnung: Gipsfaserplatten 2-lagig (BSK)
Gipsfaserplatten 2-lagig (BSK) | WUN-H2-E00-F09 | CEILING | Installationshöhe 0.164 m | 1115Dfl0000005210/02 | m² | Trockenbauarbeiten | 2 | 0.164 | 0 | 1 | Bekleidung | Installationshöhe | 0 | 0 | NEW | 3.1 | Pset_CoveringCommon - FireRating: -; AcousticRating: -; AllplanAttributes - ash_lichte Raumhöhe: 3.100000
Gipsfaserplatten 2-lagig (BSK) | WUN-H2-E00-F09 | CEILING | A1 0.1 m | 1115Dfl0000005210/03 | m² | Trockenbauarbeiten | 3 | 0.1 | 0 | 1 | Bekleidung | A1 | 0 | 0 | NEW | 3.1 | Pset_CoveringCommon - FireRating: -; AcousticRating: -; AllplanAttributes - ash_lichte Raumhöhe: 3.100000
Gipsfaserplatten 2-lagig (BSK) | WUN-H2-E00-F09 | CEILING | D1 0.001 m | 1115Dfl0000005210/04 | m² | Maler- und Lackierarbeiten | 4 | 0.001 | 0 | 1 | Bekleidung | D1 | 0 | 0 | NEW | 3.1 | AllplanAttributes - ash_lichte Raumhöhe: 3.100000
Handlauf | WUN-H2-E00-F04 | CLADDING | 97 0.001 m | 1115Sfl0000092667/02 | m² | Maler- und Lackierarbeiten | 2 | 0.001 | 0 | 1 | Seitenfläche | 97 | 0 | 0 | NEW | AllplanAttributes - Bezeichnung: Handlauf
Handlauf | WUN-H2-E00-F04 | CLADDING | 97 0.001 m | 1115Sfl0000093249/02 | m² | Maler- und Lackierarbeiten | 2 | 0.001 | 0 | 1 | Seitenfläche | 97 | 0 | 0 | NEW | AllplanAttributes - Bezeichnung: Handlauf
Handlauf | WUN-H2-E00-F04 | CLADDING | 97 0.001 m | 1115Sfl0000092958/02 | m² | Maler- und Lackierarbeiten | 2 | 0.001 | 0 | 1 | Seitenfläche | 97 | 0 | 0 | NEW | AllplanAttributes - Bezeichnung: Handlauf
PVC Bahnenware Holzoptik | WUN-H2-E00-F04 | FLOORING | Ku1 0.2 m | 1115Bfl0000005028/01 | m² | Bodenbelagsarbeiten | 1 | 0.2 | 0 | 1 | Bodenfläche | Ku1 | 0 | 0 | NEW | AllplanAttributes - Bezeichnung: PVC Bahnenware Holzoptik; Raumnr. Bauherr: 2.11_A2_02; ash B_Aufbau: B1; ash B_Rutschhemmung: R9
Gipsfaserplatten 2-lagig (BSK) | WUN-H2-E00-F04 | CEILING | layer 0.036 m | 1115Dfl0000028849/01 | m² | Trockenbauarbeiten | 1 | 0.036 | 0 | 1 | Deckenfläche |  | 0 | 0 | NEW | 2.5 | AllplanAttributes - Bezeichnung: Gipsfaserplatten 2-lagig (BSK)
Gipsfaserplatten 2-lagig (BSK) | WUN-H2-E00-F04 | CEILING | Installationshöhe 0.714 m | 1115Dfl0000028849/02 | m² | Trockenbauarbeiten | 2 | 0.714 | 0 | 1 | Bekleidung | Installationshöhe | 0 | 0 | NEW | 2.5 | Pset_CoveringCommon - FireRating: für korrekte FläVisu; AllplanAttributes - ash_lichte Raumhöhe: 2.500000
Gipsfaserplatten 2-lagig (BSK) | WUN-H2-E00-F04 | CEILING | Aa 0.15 m | 1115Dfl0000028849/03 | m² | Trockenbauarbeiten | 3 | 0.15 | 0 | 1 | Bekleidung | Aa | 0 | 0 | NEW | 2.5 | AllplanAttributes - ash_lichte Raumhöhe: 2.500000; Pset_CoveringCommon - AcousticRating: -
Gipsfaserplatten 2-lagig (BSK) | WUN-H2-E00-F04 | CEILING | D1 0.001 m | 1115Dfl0000028849/04 | m² | Maler- und Lackierarbeiten | 4 | 0.001 | 0 | 1 | Bekleidung | D1 | 0 | 0 | NEW | 2.5 | AllplanAttributes - ash_lichte Raumhöhe: 2.500000
Gipsfaserplatten 2-lagig (BSK) | WUN-H2-E00-F04 | CEILING | layer 0.036 m | 1115Dfl0813939064/01 | m² | Trockenbauarbeiten | 1 | 0.036 | 0 | 1 | Deckenfläche |  | 0 | 0 | NEW | 2.5 | AllplanAttributes - Bezeichnung: Gipsfaserplatten 2-lagig (BSK)
Gipsfaserplatten 2-lagig (BSK) | WUN-H2-E00-F04 | CEILING | Installationshöhe 0.714 m | 1115Dfl0813939064/02 | m² | Trockenbauarbeiten | 2 | 0.714 | 0 | 1 | Bekleidung | Installationshöhe | 0 | 0 | NEW | 2.5 | Pset_CoveringCommon - FireRating: für korrekte FläVisu; AllplanAttributes - ash_lichte Raumhöhe: 2.500000
Gipsfaserplatten 2-lagig (BSK) | WUN-H2-E00-F04 | CEILING | A1 0.15 m | 1115Dfl0813939064/03 | m² | Trockenbauarbeiten | 3 | 0.15 | 0 | 1 | Bekleidung | A1 | 0 | 0 | NEW | 2.5 | AllplanAttributes - ash_lichte Raumhöhe: 2.500000; Pset_CoveringCommon - AcousticRating: -
Gipsfaserplatten 2-lagig (BSK) | WUN-H2-E00-F04 | CEILING | D1 0.001 m | 1115Dfl0813939064/04 | m² | Maler- und Lackierarbeiten | 4 | 0.001 | 0 | 1 | Bekleidung | D1 | 0 | 0 | NEW | 2.5 | AllplanAttributes - ash_lichte Raumhöhe: 2.500000
Gipsfaserplatten 2-lagig (BSK) | WUN-H2-E00-F04 | CEILING | layer 0.036 m | 1115Dfl0813977962/01 | m² | Trockenbauarbeiten | 1 | 0.036 | 0 | 1 | Deckenfläche |  | 0 | 0 | NEW | 3.1 | AllplanAttributes - Bezeichnung: Gipsfaserplatten 2-lagig (BSK)
Gipsfaserplatten 2-lagig (BSK) | WUN-H2-E00-F04 | CEILING | Installationshöhe 0.164 m | 1115Dfl0813977962/02 | m² | Trockenbauarbeiten | 2 | 0.164 | 0 | 1 | Bekleidung | Installationshöhe | 0 | 0 | NEW | 3.1 | Pset_CoveringCommon - FireRating: -; AcousticRating: -; AllplanAttributes - ash_lichte Raumhöhe: 3.100000
Gipsfaserplatten 2-lagig (BSK) | WUN-H2-E00-F04 | CEILING | A1 0.1 m | 1115Dfl0813977962/03 | m² | Trockenbauarbeiten | 3 | 0.1 | 0 | 1 | Bekleidung | A1 | 0 | 0 | NEW | 3.1 | Pset_CoveringCommon - FireRating: -; AcousticRating: -; AllplanAttributes - ash_lichte Raumhöhe: 3.100000
Gipsfaserplatten 2-lagig (BSK) | WUN-H2-E00-F04 | CEILING | D1 0.001 m | 1115Dfl0813977962/04 | m² | Maler- und Lackierarbeiten | 4 | 0.001 | 0 | 1 | Bekleidung | D1 | 0 | 0 | NEW | 3.1 | AllplanAttributes - ash_lichte Raumhöhe: 3.100000
Handlauf | WUN-H2-E00-T01a | CLADDING | 97 0.001 m | 1115Sfl0000085357/02 | m² | Maler- und Lackierarbeiten | 2 | 0.001 | 0 | 1 | Seitenfläche | 97 | 0 | 0 | NEW | AllplanAttributes - Bezeichnung: Handlauf
Handlauf | WUN-H2-E00-T01a | CLADDING | 97 0.001 m | 1115Sfl0000088011/02 | m² | Maler- und Lackierarbeiten | 2 | 0.001 | 0 | 1 | Seitenfläche | 97 | 0 | 0 | NEW | AllplanAttributes - Bezeichnung: Handlauf
Sauberlaufzone | WUN-H2-E00-T01a | FLOORING | SL 0.2 m | 1115Bfl0813975816/01 | m² | Bodenbelagsarbeiten | 1 | 0.2 | 0 | 1 | Bodenfläche | SL | 0 | 0 | NEW | AllplanAttributes - Bezeichnung: Sauberlaufzone; Raumnr. Bauherr: 2.11_A2_02; ash B_Aufbau: B13
Fliesen Großformat | WUN-H2-E00-T01a | FLOORING | Fl12 0.2 m | 1115Bfl0000116946/01 | m² | Bodenbelagsarbeiten | 1 | 0.2 | 0 | 1 | Bodenfläche | Fl12 | 0 | 0 | NEW | AllplanAttributes - Bezeichnung: Fliesen Großformat; Raumnr. Bauherr: 2.11_A2_02; ash B_Aufbau: B4; ash B_Rutschhemmung: R10
Sichtbetonklasse SB3 | WUN-H2-E00-T01a | CLADDING | 03 0.001 m | 1115Sfl0813979241/02 | m² | Putz- und Stuckarbeiten | 2 | 0.001 | 0 | 1 | Seitenfläche | 03 | 0 | 0 | NEW | AllplanAttributes - Bezeichnung: Sichtbetonklasse SB3
Gipsfaserplatten 2-lagig (BSK) | WUN-H2-E00-T01a | CEILING | layer 0.036 m | 1115Dfl0813939223/01 | m² | Trockenbauarbeiten | 1 | 0.036 | 0 | 1 | Deckenfläche |  | 0 | 0 | NEW | 2.75 | AllplanAttributes - Bezeichnung: Gipsfaserplatten 2-lagig (BSK)
Gipsfaserplatten 2-lagig (BSK) | WUN-H2-E00-T01a | CEILING | Installationshöhe 0.414 m | 1115Dfl0813939223/02 | m² | Trockenbauarbeiten | 2 | 0.414 | 0 | 1 | Bekleidung | Installationshöhe | 0 | 0 | NEW | 2.75 | Pset_CoveringCommon - FireRating: für korrekte FläVisu; AllplanAttributes - ash_lichte Raumhöhe: 2.750000
Gipsfaserplatten 2-lagig (BSK) | WUN-H2-E00-T01a | CEILING | Aa 0.2 m | 1115Dfl0813939223/03 | m² | Trockenbauarbeiten | 3 | 0.2 | 0 | 1 | Bekleidung | Aa | 0 | 0 | NEW | 2.75 | Pset_CoveringCommon - FireRating: F60; AcousticRating: -; AllplanAttributes - ash_lichte Raumhöhe: 2.750000
Gipsfaserplatten 2-lagig (BSK) | WUN-H2-E00-T01a | CEILING | D1 0.001 m | 1115Dfl0813939223/04 | m² | Maler- und Lackierarbeiten | 4 | 0.001 | 0 | 1 | Bekleidung | D1 | 0 | 0 | NEW | 2.75 | AllplanAttributes - ash_lichte Raumhöhe: 2.750000
Gipsfaserplatten 2-lagig (BSK) | WUN-H2-E00-T01a | CEILING | layer 0.036 m | 1115Dfl0000005140/01 | m² | Trockenbauarbeiten | 1 | 0.036 | 0 | 1 | Deckenfläche |  | 0 | 0 | NEW | 2.75 | AllplanAttributes - Bezeichnung: Gipsfaserplatten 2-lagig (BSK)
Gipsfaserplatten 2-lagig (BSK) | WUN-H2-E00-T01a | CEILING | Installationshöhe 0.414 m | 1115Dfl0000005140/02 | m² | Trockenbauarbeiten | 2 | 0.414 | 0 | 1 | Bekleidung | Installationshöhe | 0 | 0 | NEW | 2.75 | Pset_CoveringCommon - FireRating: für korrekte FläVisu; AllplanAttributes - ash_lichte Raumhöhe: 2.750000
Gipsfaserplatten 2-lagig (BSK) | WUN-H2-E00-T01a | CEILING | A1 0.2 m | 1115Dfl0000005140/03 | m² | Trockenbauarbeiten | 3 | 0.2 | 0 | 1 | Bekleidung | A1 | 0 | 0 | NEW | 2.75 | Pset_CoveringCommon - FireRating: F60; AcousticRating: -; AllplanAttributes - ash_lichte Raumhöhe: 2.750000
Gipsfaserplatten 2-lagig (BSK) | WUN-H2-E00-T01a | CEILING | D1 0.001 m | 1115Dfl0000005140/04 | m² | Maler- und Lackierarbeiten | 4 | 0.001 | 0 | 1 | Bekleidung | D1 | 0 | 0 | NEW | 2.75 | AllplanAttributes - ash_lichte Raumhöhe: 2.750000
Fliesen Großformat | WUN-H2-E00-F07 | FLOORING | F12 0.2 m | 1115Bfl0000116557/01 | m² | Bodenbelagsarbeiten | 1 | 0.2 | 0 | 1 | Bodenfläche | F12 | 0 | 0 | NEW | AllplanAttributes - Bezeichnung: Fliesen Großformat; Raumnr. Bauherr: 2.11_A2_02; ash B_Aufbau: B4; ash B_Rutschhemmung: R10
 | WUN-H2-E00-F07 | FLOORING | F12 0.06 m | 1115Bfl0000106714/01 | m² | Bodenbelagsarbeiten | 1 | 0.06 | 0 | 1 | Bodenfläche | F12 | 0 | 0 | NEW | AllplanAttributes - Raumnr. Bauherr: 2.11_A2_02; ash B_Aufbau: B6; ash B_Rutschhemmung: R10
Sichtbetonklasse SB3 | WUN-H2-E00-F07 | CLADDING | 03 0.001 m | 1115Sfl0813979242/02 | m² | Putz- und Stuckarbeiten | 2 | 0.001 | 0 | 1 | Seitenfläche | 03 | 0 | 0 | NEW | AllplanAttributes - Bezeichnung: Sichtbetonklasse SB3
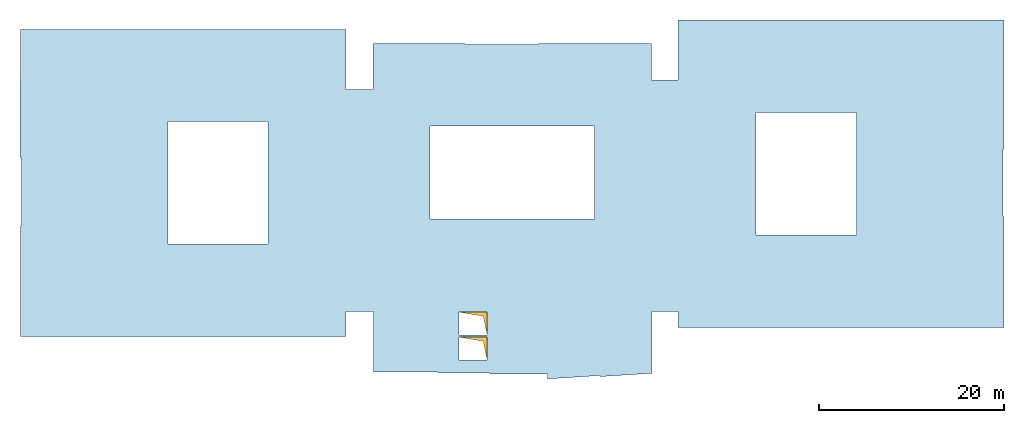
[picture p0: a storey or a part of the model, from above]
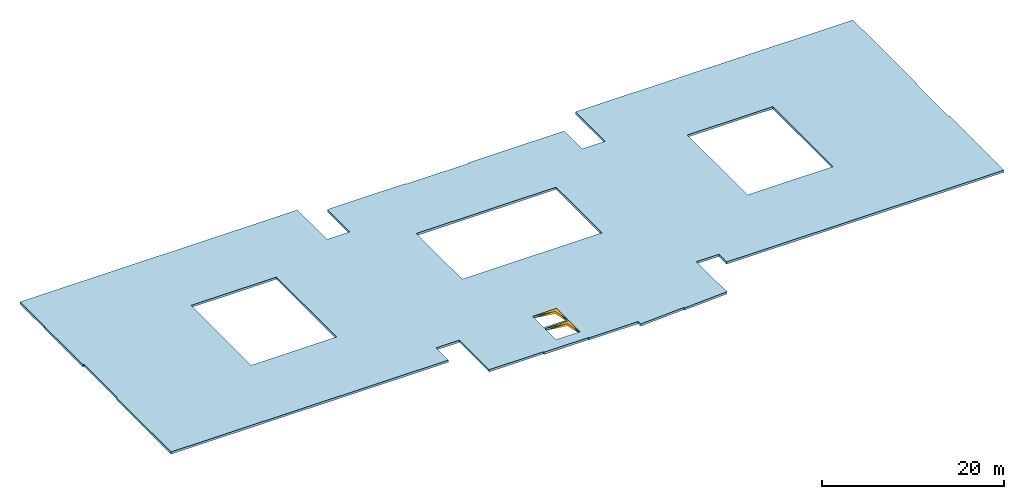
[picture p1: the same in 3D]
Properties of the parts of a building model (IFC4), part 18 of 80

# IfcCovering (3945)
Name | In | PredefinedType | Material | Allright_Bauteil_ID | Abrechnungsart | Gewerk | Schichtnummer | Schichtdicke (m) | Dicke (m) | Faktor | Objektname | AllplanAttributes, Material | Bezugshöhe | Deltahöhe | Status | D_lichte Raumhöhe [Zahl] (m)
a-sh Abschluss Abhangdecke | H2 Ebene 0 | CEILING | D1 | 1116HWa0001188133 | m² |  |  |  |  |  | Gesamtwand |  |  |  | NEW | AllplanAttributes - Bezeichnung: a-sh Abschluss Abhangdecke; Attributset-Objekt: Covering; Object Layer Attributes #1, 2D Interaktion: yes; Object Layer Attributes #1, Gewerk: Trockenbauarbeiten; Object Layer Attributes #1, Material: A; Object Layer Attributes #1, Attributset-Objekt: Covering; Object Layer Attributes #1, Allright_Bauteil_ID: 1116Wa 0001188134; Object Layer Attributes #1, Abrechnungsart: m²; Object Layer Attributes #1, Objektname: Wand; Pset_CoveringCommon - IsExternal: no; FireRating: -; ThermalTransmittance: 0 W/K/m2; Reference: Reference
a-sh Abschluss Abhangdecke | H2 Ebene 0 | CEILING | D1 | 1116HWa0001188142 | m² |  |  |  |  |  | Gesamtwand |  |  |  | NEW | AllplanAttributes - Bezeichnung: a-sh Abschluss Abhangdecke; Attributset-Objekt: Covering; Object Layer Attributes #1, 2D Interaktion: yes; Object Layer Attributes #1, Gewerk: Trockenbauarbeiten; Object Layer Attributes #1, Material: A; Object Layer Attributes #1, Attributset-Objekt: Covering; Object Layer Attributes #1, Allright_Bauteil_ID: 1116Wa 0001188143; Object Layer Attributes #1, Abrechnungsart: m²; Object Layer Attributes #1, Objektname: Wand; Pset_CoveringCommon - IsExternal: no; FireRating: -; ThermalTransmittance: 0 W/K/m2; Reference: Reference
a-sh Abschluss Abhangdecke | H2 Ebene 0 | CEILING |  | 1116HWa0001188147 | m² |  |  |  |  |  | Gesamtwand |  |  |  | NEW | AllplanAttributes - Bezeichnung: a-sh Abschluss Abhangdecke; Attributset-Objekt: Covering; Object Layer Attributes #1, 2D Interaktion: yes; Object Layer Attributes #1, Gewerk: Trockenbauarbeiten; Object Layer Attributes #1, Material: A; Object Layer Attributes #1, Attributset-Objekt: Covering; Object Layer Attributes #1, Allright_Bauteil_ID: 1116Wa 0001188148; Object Layer Attributes #1, Abrechnungsart: m²; Object Layer Attributes #1, Objektname: Wand; Pset_CoveringCommon - IsExternal: no; FireRating: -; ThermalTransmittance: 0 W/K/m2; Reference: Reference
a-sh Abschluss Abhangdecke | H2 Ebene 0 | CEILING |  | 1116HWa0001188152 | m² |  |  |  |  |  | Gesamtwand |  |  |  | NEW | AllplanAttributes - Bezeichnung: a-sh Abschluss Abhangdecke; Attributset-Objekt: Covering; Object Layer Attributes #1, 2D Interaktion: yes; Object Layer Attributes #1, Gewerk: Trockenbauarbeiten; Object Layer Attributes #1, Material: A; Object Layer Attributes #1, Attributset-Objekt: Covering; Object Layer Attributes #1, Allright_Bauteil_ID: 1116Wa 0001188153; Object Layer Attributes #1, Abrechnungsart: m²; Object Layer Attributes #1, Objektname: Wand; Pset_CoveringCommon - IsExternal: no; FireRating: -; ThermalTransmittance: 0 W/K/m2; Reference: Reference
a-sh Abschluss Abhangdecke | H2 Ebene 0 | CEILING |  | 1116HWa0001188157 | m² |  |  |  |  |  | Gesamtwand |  |  |  | NEW | AllplanAttributes - Bezeichnung: a-sh Abschluss Abhangdecke; Attributset-Objekt: Covering; Object Layer Attributes #1, 2D Interaktion: yes; Object Layer Attributes #1, Gewerk: Trockenbauarbeiten; Object Layer Attributes #1, Material: A; Object Layer Attributes #1, Attributset-Objekt: Covering; Object Layer Attributes #1, Allright_Bauteil_ID: 1116Wa 0001188158; Object Layer Attributes #1, Abrechnungsart: m²; Object Layer Attributes #1, Objektname: Wand; Pset_CoveringCommon - IsExternal: no; FireRating: -; ThermalTransmittance: 0 W/K/m2; Reference: Reference
a-sh Abschluss Abhangdecke | H2 Ebene 0 | CEILING |  | 1116HWa0001188162 | m² |  |  |  |  |  | Gesamtwand |  |  |  | NEW | AllplanAttributes - Bezeichnung: a-sh Abschluss Abhangdecke; Attributset-Objekt: Covering; Object Layer Attributes #1, 2D Interaktion: yes; Object Layer Attributes #1, Gewerk: Trockenbauarbeiten; Object Layer Attributes #1, Material: A; Object Layer Attributes #1, Attributset-Objekt: Covering; Object Layer Attributes #1, Allright_Bauteil_ID: 1116Wa 0001188163; Object Layer Attributes #1, Abrechnungsart: m²; Object Layer Attributes #1, Objektname: Wand; Pset_CoveringCommon - IsExternal: no; FireRating: -; ThermalTransmittance: 0 W/K/m2; Reference: Reference
a-sh Abschluss Abhangdecke | H2 Ebene 0 | CEILING |  | 1116HWa0001188167 | m² |  |  |  |  |  | Gesamtwand |  |  |  | NEW | AllplanAttributes - Bezeichnung: a-sh Abschluss Abhangdecke; Attributset-Objekt: Covering; Object Layer Attributes #1, 2D Interaktion: yes; Object Layer Attributes #1, Gewerk: Trockenbauarbeiten; Object Layer Attributes #1, Material: A; Object Layer Attributes #1, Attributset-Objekt: Covering; Object Layer Attributes #1, Allright_Bauteil_ID: 1116Wa 0001188168; Object Layer Attributes #1, Abrechnungsart: m²; Object Layer Attributes #1, Objektname: Wand; Pset_CoveringCommon - IsExternal: no; FireRating: -; ThermalTransmittance: 0 W/K/m2; Reference: Reference
a-sh Abschluss Abhangdecke | H2 Ebene 0 | CEILING |  | 1116HWa0001188172 | m² |  |  |  |  |  | Gesamtwand |  |  |  | NEW | AllplanAttributes - Bezeichnung: a-sh Abschluss Abhangdecke; Attributset-Objekt: Covering; Object Layer Attributes #1, 2D Interaktion: yes; Object Layer Attributes #1, Gewerk: Trockenbauarbeiten; Object Layer Attributes #1, Material: A; Object Layer Attributes #1, Attributset-Objekt: Covering; Object Layer Attributes #1, Allright_Bauteil_ID: 1116Wa 0001188173; Object Layer Attributes #1, Abrechnungsart: m²; Object Layer Attributes #1, Objektname: Wand; Pset_CoveringCommon - IsExternal: no; FireRating: -; ThermalTransmittance: 0 W/K/m2; Reference: Reference
a-sh Abschluss Abhangdecke | H2 Ebene 0 | CEILING |  | 1116HWa0001188177 | m² |  |  |  |  |  | Gesamtwand |  |  |  | NEW | AllplanAttributes - Bezeichnung: a-sh Abschluss Abhangdecke; Attributset-Objekt: Covering; Object Layer Attributes #1, 2D Interaktion: yes; Object Layer Attributes #1, Gewerk: Trockenbauarbeiten; Object Layer Attributes #1, Material: A; Object Layer Attributes #1, Attributset-Objekt: Covering; Object Layer Attributes #1, Allright_Bauteil_ID: 1116Wa 0001188178; Object Layer Attributes #1, Abrechnungsart: m²; Object Layer Attributes #1, Objektname: Wand; Pset_CoveringCommon - IsExternal: no; FireRating: -; ThermalTransmittance: 0 W/K/m2; Reference: Reference
a-sh Abschluss Abhangdecke | H2 Ebene 0 | CEILING |  | 1116HWa0001188182 | m² |  |  |  |  |  | Gesamtwand |  |  |  | NEW | AllplanAttributes - Bezeichnung: a-sh Abschluss Abhangdecke; Attributset-Objekt: Covering; Object Layer Attributes #1, 2D Interaktion: yes; Object Layer Attributes #1, Gewerk: Trockenbauarbeiten; Object Layer Attributes #1, Material: A; Object Layer Attributes #1, Attributset-Objekt: Covering; Object Layer Attributes #1, Allright_Bauteil_ID: 1116Wa 0001188183; Object Layer Attributes #1, Abrechnungsart: m²; Object Layer Attributes #1, Objektname: Wand; Pset_CoveringCommon - IsExternal: no; FireRating: -; ThermalTransmittance: 0 W/K/m2; Reference: Reference
a-sh Abschluss Abhangdecke | H2 Ebene 0 | CEILING |  | 1116HWa0001188187 | m² |  |  |  |  |  | Gesamtwand |  |  |  | NEW | AllplanAttributes - Bezeichnung: a-sh Abschluss Abhangdecke; Attributset-Objekt: Covering; Object Layer Attributes #1, 2D Interaktion: yes; Object Layer Attributes #1, Gewerk: Trockenbauarbeiten; Object Layer Attributes #1, Material: A; Object Layer Attributes #1, Attributset-Objekt: Covering; Object Layer Attributes #1, Allright_Bauteil_ID: 1116Wa 0001188188; Object Layer Attributes #1, Abrechnungsart: m²; Object Layer Attributes #1, Objektname: Wand; Pset_CoveringCommon - IsExternal: no; FireRating: -; ThermalTransmittance: 0 W/K/m2; Reference: Reference
a-sh Abschluss Abhangdecke | H2 Ebene 0 | CEILING |  | 1116HWa0001188192 | m² |  |  |  |  |  | Gesamtwand |  |  |  | NEW | AllplanAttributes - Bezeichnung: a-sh Abschluss Abhangdecke; Attributset-Objekt: Covering; Object Layer Attributes #1, 2D Interaktion: yes; Object Layer Attributes #1, Gewerk: Trockenbauarbeiten; Object Layer Attributes #1, Material: A; Object Layer Attributes #1, Attributset-Objekt: Covering; Object Layer Attributes #1, Allright_Bauteil_ID: 1116Wa 0001188193; Object Layer Attributes #1, Abrechnungsart: m²; Object Layer Attributes #1, Objektname: Wand; Pset_CoveringCommon - IsExternal: no; FireRating: -; ThermalTransmittance: 0 W/K/m2; Reference: Reference
a-sh Abschluss Abhangdecke | H2 Ebene 0 | CEILING |  | 1116HWa0001188197 | m² |  |  |  |  |  | Gesamtwand |  |  |  | NEW | AllplanAttributes - Bezeichnung: a-sh Abschluss Abhangdecke; Attributset-Objekt: Covering; Object Layer Attributes #1, 2D Interaktion: yes; Object Layer Attributes #1, Gewerk: Trockenbauarbeiten; Object Layer Attributes #1, Material: A; Object Layer Attributes #1, Attributset-Objekt: Covering; Object Layer Attributes #1, Allright_Bauteil_ID: 1116Wa 0001188198; Object Layer Attributes #1, Abrechnungsart: m²; Object Layer Attributes #1, Objektname: Wand; Pset_CoveringCommon - IsExternal: no; FireRating: -; ThermalTransmittance: 0 W/K/m2; Reference: Reference
a-sh Abschluss Abhangdecke | H2 Ebene 0 | CEILING |  | 1116HWa0001188202 | m² |  |  |  |  |  | Gesamtwand |  |  |  | NEW | AllplanAttributes - Bezeichnung: a-sh Abschluss Abhangdecke; Attributset-Objekt: Covering; Object Layer Attributes #1, 2D Interaktion: yes; Object Layer Attributes #1, Gewerk: Trockenbauarbeiten; Object Layer Attributes #1, Material: A; Object Layer Attributes #1, Attributset-Objekt: Covering; Object Layer Attributes #1, Allright_Bauteil_ID: 1116Wa 0001188203; Object Layer Attributes #1, Abrechnungsart: m²; Object Layer Attributes #1, Objektname: Wand; Pset_CoveringCommon - IsExternal: no; FireRating: -; ThermalTransmittance: 0 W/K/m2; Reference: Reference
a-sh Abschluss Abhangdecke | H2 Ebene 0 | CEILING |  | 1116HWa0001188207 | m² |  |  |  |  |  | Gesamtwand |  |  |  | NEW | AllplanAttributes - Bezeichnung: a-sh Abschluss Abhangdecke; Attributset-Objekt: Covering; Object Layer Attributes #1, 2D Interaktion: yes; Object Layer Attributes #1, Gewerk: Trockenbauarbeiten; Object Layer Attributes #1, Material: A; Object Layer Attributes #1, Attributset-Objekt: Covering; Object Layer Attributes #1, Allright_Bauteil_ID: 1116Wa 0001188208; Object Layer Attributes #1, Abrechnungsart: m²; Object Layer Attributes #1, Objektname: Wand; Pset_CoveringCommon - IsExternal: no; FireRating: -; ThermalTransmittance: 0 W/K/m2; Reference: Reference
a-sh Abschluss Abhangdecke | H2 Ebene 0 | CEILING |  | 1116HWa0001188212 | m² |  |  |  |  |  | Gesamtwand |  |  |  | NEW | AllplanAttributes - Bezeichnung: a-sh Abschluss Abhangdecke; Attributset-Objekt: Covering; Object Layer Attributes #1, 2D Interaktion: yes; Object Layer Attributes #1, Gewerk: Trockenbauarbeiten; Object Layer Attributes #1, Material: A; Object Layer Attributes #1, Attributset-Objekt: Covering; Object Layer Attributes #1, Allright_Bauteil_ID: 1116Wa 0001188213; Object Layer Attributes #1, Abrechnungsart: m²; Object Layer Attributes #1, Objektname: Wand; Pset_CoveringCommon - IsExternal: no; FireRating: -; ThermalTransmittance: 0 W/K/m2; Reference: Reference
a-sh Abschluss Abhangdecke | H2 Ebene 0 | CEILING |  | 1116HWa0001188217 | m² |  |  |  |  |  | Gesamtwand |  |  |  | NEW | AllplanAttributes - Bezeichnung: a-sh Abschluss Abhangdecke; Attributset-Objekt: Covering; Object Layer Attributes #1, 2D Interaktion: yes; Object Layer Attributes #1, Gewerk: Trockenbauarbeiten; Object Layer Attributes #1, Material: A; Object Layer Attributes #1, Attributset-Objekt: Covering; Object Layer Attributes #1, Allright_Bauteil_ID: 1116Wa 0001188218; Object Layer Attributes #1, Abrechnungsart: m²; Object Layer Attributes #1, Objektname: Wand; Pset_CoveringCommon - IsExternal: no; FireRating: -; ThermalTransmittance: 0 W/K/m2; Reference: Reference
a-sh Abschluss Abhangdecke | H2 Ebene 0 | CEILING |  | 1116HWa0001188222 | m² |  |  |  |  |  | Gesamtwand |  |  |  | NEW | AllplanAttributes - Bezeichnung: a-sh Abschluss Abhangdecke; Attributset-Objekt: Covering; Object Layer Attributes #1, 2D Interaktion: yes; Object Layer Attributes #1, Gewerk: Trockenbauarbeiten; Object Layer Attributes #1, Material: A; Object Layer Attributes #1, Attributset-Objekt: Covering; Object Layer Attributes #1, Allright_Bauteil_ID: 1116Wa 0001188223; Object Layer Attributes #1, Abrechnungsart: m²; Object Layer Attributes #1, Objektname: Wand; Pset_CoveringCommon - IsExternal: no; FireRating: -; ThermalTransmittance: 0 W/K/m2; Reference: Reference
a-sh Abschluss Abhangdecke | H2 Ebene 0 | CEILING |  | 1116HWa0001188227 | m² |  |  |  |  |  | Gesamtwand |  |  |  | NEW | AllplanAttributes - Bezeichnung: a-sh Abschluss Abhangdecke; Attributset-Objekt: Covering; Object Layer Attributes #1, 2D Interaktion: yes; Object Layer Attributes #1, Gewerk: Trockenbauarbeiten; Object Layer Attributes #1, Material: A; Object Layer Attributes #1, Attributset-Objekt: Covering; Object Layer Attributes #1, Allright_Bauteil_ID: 1116Wa 0001188228; Object Layer Attributes #1, Abrechnungsart: m²; Object Layer Attributes #1, Objektname: Wand; Pset_CoveringCommon - IsExternal: no; FireRating: -; ThermalTransmittance: 0 W/K/m2; Reference: Reference
a-sh Abschluss Abhangdecke | H2 Ebene 0 | CEILING |  | 1116HWa0001188232 | m² |  |  |  |  |  | Gesamtwand |  |  |  | NEW | AllplanAttributes - Bezeichnung: a-sh Abschluss Abhangdecke; Attributset-Objekt: Covering; Object Layer Attributes #1, 2D Interaktion: yes; Object Layer Attributes #1, Gewerk: Trockenbauarbeiten; Object Layer Attributes #1, Material: A; Object Layer Attributes #1, Attributset-Objekt: Covering; Object Layer Attributes #1, Allright_Bauteil_ID: 1116Wa 0001188233; Object Layer Attributes #1, Abrechnungsart: m²; Object Layer Attributes #1, Objektname: Wand; Pset_CoveringCommon - IsExternal: no; FireRating: -; ThermalTransmittance: 0 W/K/m2; Reference: Reference
a-sh Abschluss Abhangdecke | H2 Ebene 0 | CEILING |  | 1116HWa0001188237 | m² |  |  |  |  |  | Gesamtwand |  |  |  | NEW | AllplanAttributes - Bezeichnung: a-sh Abschluss Abhangdecke; Attributset-Objekt: Covering; Object Layer Attributes #1, 2D Interaktion: yes; Object Layer Attributes #1, Gewerk: Trockenbauarbeiten; Object Layer Attributes #1, Material: A; Object Layer Attributes #1, Attributset-Objekt: Covering; Object Layer Attributes #1, Allright_Bauteil_ID: 1116Wa 0001188238; Object Layer Attributes #1, Abrechnungsart: m²; Object Layer Attributes #1, Objektname: Wand; Pset_CoveringCommon - IsExternal: no; FireRating: -; ThermalTransmittance: 0 W/K/m2; Reference: Reference
a-sh Abschluss Abhangdecke | H2 Ebene 0 | CEILING |  | 1116HWa0001188242 | m² |  |  |  |  |  | Gesamtwand |  |  |  | NEW | AllplanAttributes - Bezeichnung: a-sh Abschluss Abhangdecke; Attributset-Objekt: Covering; Object Layer Attributes #1, 2D Interaktion: yes; Object Layer Attributes #1, Gewerk: Trockenbauarbeiten; Object Layer Attributes #1, Material: A; Object Layer Attributes #1, Attributset-Objekt: Covering; Object Layer Attributes #1, Allright_Bauteil_ID: 1116Wa 0001188243; Object Layer Attributes #1, Abrechnungsart: m²; Object Layer Attributes #1, Objektname: Wand; Pset_CoveringCommon - IsExternal: no; FireRating: -; ThermalTransmittance: 0 W/K/m2; Reference: Reference
a-sh Abschluss Abhangdecke | H2 Ebene 0 | CEILING |  | 1116HWa0001188247 | m² |  |  |  |  |  | Gesamtwand |  |  |  | NEW | AllplanAttributes - Bezeichnung: a-sh Abschluss Abhangdecke; Attributset-Objekt: Covering; Object Layer Attributes #1, 2D Interaktion: yes; Object Layer Attributes #1, Gewerk: Trockenbauarbeiten; Object Layer Attributes #1, Material: A; Object Layer Attributes #1, Attributset-Objekt: Covering; Object Layer Attributes #1, Allright_Bauteil_ID: 1116Wa 0001188248; Object Layer Attributes #1, Abrechnungsart: m²; Object Layer Attributes #1, Objektname: Wand; Pset_CoveringCommon - IsExternal: no; FireRating: -; ThermalTransmittance: 0 W/K/m2; Reference: Reference
a-sh Abschluss Abhangdecke | H2 Ebene 0 | CEILING |  | 1116HWa0001188252 | m² |  |  |  |  |  | Gesamtwand |  |  |  | NEW | AllplanAttributes - Bezeichnung: a-sh Abschluss Abhangdecke; Attributset-Objekt: Covering; Object Layer Attributes #1, 2D Interaktion: yes; Object Layer Attributes #1, Gewerk: Trockenbauarbeiten; Object Layer Attributes #1, Material: A; Object Layer Attributes #1, Attributset-Objekt: Covering; Object Layer Attributes #1, Allright_Bauteil_ID: 1116Wa 0001188253; Object Layer Attributes #1, Abrechnungsart: m²; Object Layer Attributes #1, Objektname: Wand; Pset_CoveringCommon - IsExternal: no; FireRating: -; ThermalTransmittance: 0 W/K/m2; Reference: Reference
a-sh Abschluss Abhangdecke | H2 Ebene 0 | CEILING |  | 1116HWa0001188257 | m² |  |  |  |  |  | Gesamtwand |  |  |  | NEW | AllplanAttributes - Bezeichnung: a-sh Abschluss Abhangdecke; Attributset-Objekt: Covering; Object Layer Attributes #1, 2D Interaktion: yes; Object Layer Attributes #1, Gewerk: Trockenbauarbeiten; Object Layer Attributes #1, Material: A; Object Layer Attributes #1, Attributset-Objekt: Covering; Object Layer Attributes #1, Allright_Bauteil_ID: 1116Wa 0001188258; Object Layer Attributes #1, Abrechnungsart: m²; Object Layer Attributes #1, Objektname: Wand; Pset_CoveringCommon - IsExternal: no; FireRating: -; ThermalTransmittance: 0 W/K/m2; Reference: Reference
a-sh Abschluss Abhangdecke | H2 Ebene 0 | CEILING |  | 1116HWa0001188262 | m² |  |  |  |  |  | Gesamtwand |  |  |  | NEW | AllplanAttributes - Bezeichnung: a-sh Abschluss Abhangdecke; Attributset-Objekt: Covering; Object Layer Attributes #1, 2D Interaktion: yes; Object Layer Attributes #1, Gewerk: Trockenbauarbeiten; Object Layer Attributes #1, Material: A; Object Layer Attributes #1, Attributset-Objekt: Covering; Object Layer Attributes #1, Allright_Bauteil_ID: 1116Wa 0001188263; Object Layer Attributes #1, Abrechnungsart: m²; Object Layer Attributes #1, Objektname: Wand; Pset_CoveringCommon - IsExternal: no; FireRating: -; ThermalTransmittance: 0 W/K/m2; Reference: Reference
a-sh Abschluss Abhangdecke | H2 Ebene 0 | CEILING |  | 1116HWa0001188267 | m² |  |  |  |  |  | Gesamtwand |  |  |  | NEW | AllplanAttributes - Bezeichnung: a-sh Abschluss Abhangdecke; Attributset-Objekt: Covering; Object Layer Attributes #1, 2D Interaktion: yes; Object Layer Attributes #1, Gewerk: Trockenbauarbeiten; Object Layer Attributes #1, Material: A; Object Layer Attributes #1, Attributset-Objekt: Covering; Object Layer Attributes #1, Allright_Bauteil_ID: 1116Wa 0001188268; Object Layer Attributes #1, Abrechnungsart: m²; Object Layer Attributes #1, Objektname: Wand; Pset_CoveringCommon - IsExternal: no; FireRating: -; ThermalTransmittance: 0 W/K/m2; Reference: Reference
a-sh Abschluss Abhangdecke | H2 Ebene 0 | CEILING |  | 1116HWa0001188272 | m² |  |  |  |  |  | Gesamtwand |  |  |  | NEW | AllplanAttributes - Bezeichnung: a-sh Abschluss Abhangdecke; Attributset-Objekt: Covering; Object Layer Attributes #1, 2D Interaktion: yes; Object Layer Attributes #1, Gewerk: Trockenbauarbeiten; Object Layer Attributes #1, Material: A; Object Layer Attributes #1, Attributset-Objekt: Covering; Object Layer Attributes #1, Allright_Bauteil_ID: 1116Wa 0001188273; Object Layer Attributes #1, Abrechnungsart: m²; Object Layer Attributes #1, Objektname: Wand; Pset_CoveringCommon - IsExternal: no; FireRating: -; ThermalTransmittance: 0 W/K/m2; Reference: Reference
a-sh Abschluss Abhangdecke | H2 Ebene 0 | CEILING |  | 1116HWa0001188277 | m² |  |  |  |  |  | Gesamtwand |  |  |  | NEW | AllplanAttributes - Bezeichnung: a-sh Abschluss Abhangdecke; Attributset-Objekt: Covering; Object Layer Attributes #1, 2D Interaktion: yes; Object Layer Attributes #1, Gewerk: Trockenbauarbeiten; Object Layer Attributes #1, Material: A; Object Layer Attributes #1, Attributset-Objekt: Covering; Object Layer Attributes #1, Allright_Bauteil_ID: 1116Wa 0001188278; Object Layer Attributes #1, Abrechnungsart: m²; Object Layer Attributes #1, Objektname: Wand; Pset_CoveringCommon - IsExternal: no; FireRating: -; ThermalTransmittance: 0 W/K/m2; Reference: Reference
a-sh Abschluss Abhangdecke | H2 Ebene 0 | CEILING | D1 | 1116HWa0001188286 | m² |  |  |  |  |  | Gesamtwand |  |  |  | NEW | AllplanAttributes - Bezeichnung: a-sh Abschluss Abhangdecke; Attributset-Objekt: Covering; Object Layer Attributes #1, 2D Interaktion: yes; Object Layer Attributes #1, Gewerk: Trockenbauarbeiten; Object Layer Attributes #1, Material: A; Object Layer Attributes #1, Attributset-Objekt: Covering; Object Layer Attributes #1, Allright_Bauteil_ID: 1116Wa 0001188287; Object Layer Attributes #1, Abrechnungsart: m²; Object Layer Attributes #1, Objektname: Wand; Pset_CoveringCommon - IsExternal: no; FireRating: -; ThermalTransmittance: 0 W/K/m2; Reference: Reference
a-sh Abschluss Abhangdecke | H2 Ebene 0 | CEILING | D1 | 1116HWa0001188291 | m² |  |  |  |  |  | Gesamtwand |  |  |  | NEW | AllplanAttributes - Bezeichnung: a-sh Abschluss Abhangdecke; Attributset-Objekt: Covering; Object Layer Attributes #1, 2D Interaktion: yes; Object Layer Attributes #1, Gewerk: Trockenbauarbeiten; Object Layer Attributes #1, Material: A; Object Layer Attributes #1, Attributset-Objekt: Covering; Object Layer Attributes #1, Allright_Bauteil_ID: 1116Wa 0001188292; Object Layer Attributes #1, Abrechnungsart: m²; Object Layer Attributes #1, Objektname: Wand; Pset_CoveringCommon - IsExternal: no; FireRating: -; ThermalTransmittance: 0 W/K/m2; Reference: Reference
a-sh Abschluss Abhangdecke | H2 Ebene 0 | CEILING | D1 | 1116HWa0001188296 | m² |  |  |  |  |  | Gesamtwand |  |  |  | NEW | AllplanAttributes - Bezeichnung: a-sh Abschluss Abhangdecke; Attributset-Objekt: Covering; Object Layer Attributes #1, 2D Interaktion: yes; Object Layer Attributes #1, Gewerk: Trockenbauarbeiten; Object Layer Attributes #1, Material: A; Object Layer Attributes #1, Attributset-Objekt: Covering; Object Layer Attributes #1, Allright_Bauteil_ID: 1116Wa 0001188297; Object Layer Attributes #1, Abrechnungsart: m²; Object Layer Attributes #1, Objektname: Wand; Pset_CoveringCommon - IsExternal: no; FireRating: -; ThermalTransmittance: 0 W/K/m2; Reference: Reference
a-sh Abschluss Abhangdecke | H2 Ebene 0 | CEILING | D1 | 1116HWa0001188305 | m² |  |  |  |  |  | Gesamtwand |  |  |  | NEW | AllplanAttributes - Bezeichnung: a-sh Abschluss Abhangdecke; Attributset-Objekt: Covering; Object Layer Attributes #1, 2D Interaktion: yes; Object Layer Attributes #1, Gewerk: Trockenbauarbeiten; Object Layer Attributes #1, Material: A; Object Layer Attributes #1, Attributset-Objekt: Covering; Object Layer Attributes #1, Allright_Bauteil_ID: 1116Wa 0001188306; Object Layer Attributes #1, Abrechnungsart: m²; Object Layer Attributes #1, Objektname: Wand; Pset_CoveringCommon - IsExternal: no; FireRating: -; ThermalTransmittance: 0 W/K/m2; Reference: Reference
a-sh Abschluss Abhangdecke | H2 Ebene 0 | CEILING |  | 1116HWa0001188310 | m² |  |  |  |  |  | Gesamtwand |  |  |  | NEW | AllplanAttributes - Bezeichnung: a-sh Abschluss Abhangdecke; Attributset-Objekt: Covering; Object Layer Attributes #1, 2D Interaktion: yes; Object Layer Attributes #1, Gewerk: Trockenbauarbeiten; Object Layer Attributes #1, Material: A; Object Layer Attributes #1, Attributset-Objekt: Covering; Object Layer Attributes #1, Allright_Bauteil_ID: 1116Wa 0001188311; Object Layer Attributes #1, Abrechnungsart: m²; Object Layer Attributes #1, Objektname: Wand; Pset_CoveringCommon - IsExternal: no; FireRating: -; ThermalTransmittance: 0 W/K/m2; Reference: Reference
a-sh Abschluss Abhangdecke | H2 Ebene 0 | CEILING |  | 1116HWa0001188320 | m² |  |  |  |  |  | Gesamtwand |  |  |  | NEW | AllplanAttributes - Bezeichnung: a-sh Abschluss Abhangdecke; Attributset-Objekt: Covering; Object Layer Attributes #1, 2D Interaktion: yes; Object Layer Attributes #1, Gewerk: Trockenbauarbeiten; Object Layer Attributes #1, Material: A; Object Layer Attributes #1, Attributset-Objekt: Covering; Object Layer Attributes #1, Allright_Bauteil_ID: 1116Wa 0001188321; Object Layer Attributes #1, Abrechnungsart: m²; Object Layer Attributes #1, Objektname: Wand; Pset_CoveringCommon - IsExternal: no; FireRating: -; ThermalTransmittance: 0 W/K/m2; Reference: Reference
a-sh Abschluss Abhangdecke | H2 Ebene 0 | CEILING | D1 | 1116HWa0001188340 | m² |  |  |  |  |  | Gesamtwand |  |  |  | NEW | AllplanAttributes - Bezeichnung: a-sh Abschluss Abhangdecke; Attributset-Objekt: Covering; Object Layer Attributes #1, 2D Interaktion: yes; Object Layer Attributes #1, Gewerk: Trockenbauarbeiten; Object Layer Attributes #1, Material: A; Object Layer Attributes #1, Attributset-Objekt: Covering; Object Layer Attributes #1, Allright_Bauteil_ID: 1116Wa 0001188341; Object Layer Attributes #1, Abrechnungsart: m²; Object Layer Attributes #1, Objektname: Wand; Pset_CoveringCommon - IsExternal: no; FireRating: -; ThermalTransmittance: 0 W/K/m2; Reference: Reference
a-sh Abschluss Abhangdecke | H2 Ebene 0 | CEILING |  | 1116HWa0001188345 | m² |  |  |  |  |  | Gesamtwand |  |  |  | NEW | AllplanAttributes - Bezeichnung: a-sh Abschluss Abhangdecke; Attributset-Objekt: Covering; Object Layer Attributes #1, 2D Interaktion: yes; Object Layer Attributes #1, Gewerk: Trockenbauarbeiten; Object Layer Attributes #1, Material: A; Object Layer Attributes #1, Attributset-Objekt: Covering; Object Layer Attributes #1, Allright_Bauteil_ID: 1116Wa 0001188346; Object Layer Attributes #1, Abrechnungsart: m²; Object Layer Attributes #1, Objektname: Wand; Pset_CoveringCommon - IsExternal: no; FireRating: -; ThermalTransmittance: 0 W/K/m2; Reference: Reference
a-sh Abschluss Abhangdecke | H2 Ebene 0 | CEILING |  | 1116HWa0001188355 | m² |  |  |  |  |  | Gesamtwand |  |  |  | NEW | AllplanAttributes - Bezeichnung: a-sh Abschluss Abhangdecke; Attributset-Objekt: Covering; Object Layer Attributes #1, 2D Interaktion: yes; Object Layer Attributes #1, Gewerk: Trockenbauarbeiten; Object Layer Attributes #1, Material: A; Object Layer Attributes #1, Attributset-Objekt: Covering; Object Layer Attributes #1, Allright_Bauteil_ID: 1116Wa 0001188356; Object Layer Attributes #1, Abrechnungsart: m²; Object Layer Attributes #1, Objektname: Wand; Pset_CoveringCommon - IsExternal: no; FireRating: -; ThermalTransmittance: 0 W/K/m2; Reference: Reference
a-sh Abschluss Abhangdecke | H2 Ebene 0 | CEILING | D1 | 1116HWa0001188367 | m² |  |  |  |  |  | Gesamtwand |  |  |  | NEW | AllplanAttributes - Bezeichnung: a-sh Abschluss Abhangdecke; Attributset-Objekt: Covering; Object Layer Attributes #1, 2D Interaktion: yes; Object Layer Attributes #1, Gewerk: Trockenbauarbeiten; Object Layer Attributes #1, Material: A; Object Layer Attributes #1, Attributset-Objekt: Covering; Object Layer Attributes #1, Allright_Bauteil_ID: 1116Wa 0001188368; Object Layer Attributes #1, Abrechnungsart: m²; Object Layer Attributes #1, Objektname: Wand; Pset_CoveringCommon - IsExternal: no; FireRating: -; ThermalTransmittance: 0 W/K/m2; Reference: Reference
PVC Bahnenware Holzoptik | WUN-H2-E00-F09a | FLOORING | Ku1 0.2 m | 1116Bfl0000227235/01 | m² | Bodenbelagsarbeiten | 1 | 0.2 | 0 | 1 | Bodenfläche | Ku1 | 0 | 0 | NEW | AllplanAttributes - Bezeichnung: PVC Bahnenware Holzoptik; Raumnr. Bauherr: 2.11_A2_02; ash B_Aufbau: B1; ash B_Rutschhemmung: R9
Gipsfaserplatten 2-lagig (BSK) | WUN-H2-E00-F09a | CEILING | layer 0.036 m | 1116Dfl0000227234/01 | m² | Trockenbauarbeiten | 1 | 0.036 | 0 | 1 | Deckenfläche |  | 0 | 0 | NEW | 2.5 | AllplanAttributes - Bezeichnung: Gipsfaserplatten 2-lagig (BSK)
Gipsfaserplatten 2-lagig (BSK) | WUN-H2-E00-F09a | CEILING | Installationshöhe 0.714 m | 1116Dfl0000227234/02 | m² | Trockenbauarbeiten | 2 | 0.714 | 0 | 1 | Bekleidung | Installationshöhe | 0 | 0 | NEW | 2.5 | Pset_CoveringCommon - FireRating: für korrekte FläVisu; AllplanAttributes - ash_lichte Raumhöhe: 2.500000
Gipsfaserplatten 2-lagig (BSK) | WUN-H2-E00-F09a | CEILING | A1 0.15 m | 1116Dfl0000227234/03 | m² | Trockenbauarbeiten | 3 | 0.15 | 0 | 1 | Bekleidung | A1 | 0 | 0 | NEW | 2.5 | Pset_CoveringCommon - FireRating: -; AcousticRating: -; AllplanAttributes - ash_lichte Raumhöhe: 2.500000; OKFF: 0
Gipsfaserplatten 2-lagig (BSK) | WUN-H2-E00-F09a | CEILING | D1 0.001 m | 1116Dfl0000227234/04 | m² | Maler- und Lackierarbeiten | 4 | 0.001 | 0 | 1 | Bekleidung | D1 | 0 | 0 | NEW | 2.5 | AllplanAttributes - ash_lichte Raumhöhe: 2.500000
Gipsfaserplatten 2-lagig (BSK) | WUN-H2-E00-F09a | CEILING | layer 0.036 m | 1116Dfl0000543795/01 | m² | Trockenbauarbeiten | 1 | 0.036 | 0 | 1 | Deckenfläche |  | 0 | 0 | NEW | 2.5 | AllplanAttributes - Bezeichnung: Gipsfaserplatten 2-lagig (BSK)
Gipsfaserplatten 2-lagig (BSK) | WUN-H2-E00-F09a | CEILING | Installationshöhe 0.714 m | 1116Dfl0000543795/02 | m² | Trockenbauarbeiten | 2 | 0.714 | 0 | 1 | Bekleidung | Installationshöhe | 0 | 0 | NEW | 2.5 | Pset_CoveringCommon - FireRating: für korrekte FläVisu; AllplanAttributes - ash_lichte Raumhöhe: 2.500000; OKFF: 0
Gipsfaserplatten 2-lagig (BSK) | WUN-H2-E00-F09a | CEILING | Aa 0.15 m | 1116Dfl0000543795/03 | m² | Trockenbauarbeiten | 3 | 0.15 | 0 | 1 | Bekleidung | Aa | 0 | 0 | NEW | 2.5 | Pset_CoveringCommon - FireRating: -; AcousticRating: -; AllplanAttributes - ash_lichte Raumhöhe: 2.500000; OKFF: 0
Gipsfaserplatten 2-lagig (BSK) | WUN-H2-E00-F09a | CEILING | D1 0.001 m | 1116Dfl0000543795/04 | m² | Maler- und Lackierarbeiten | 4 | 0.001 | 0 | 1 | Bekleidung | D1 | 0 | 0 | NEW | 2.5 | AllplanAttributes - ash_lichte Raumhöhe: 2.500000; OKFF: 0
Gipsfaserplatten 2-lagig (BSK) | WUN-H2-E00-079 | CEILING | layer 0.036 m | 1116Dfl0000065404/01 | m² | Trockenbauarbeiten | 1 | 0.036 | 0 | 1 | Deckenfläche |  | 0 | 0 | NEW | 2.5 | AllplanAttributes - Bezeichnung: Gipsfaserplatten 2-lagig (BSK)
Gipsfaserplatten 2-lagig (BSK) | WUN-H2-E00-079 | CEILING | Installationshöhe 0.764 m | 1116Dfl0000065404/02 | m² | Trockenbauarbeiten | 2 | 0.764 | 0 | 1 | Bekleidung | Installationshöhe | 0 | 0 | NEW | 2.5 | Pset_CoveringCommon - FireRating: für korrekte FläVisu; AllplanAttributes - ash_lichte Raumhöhe: (3400-36+764+100)/1000-0
Rasterdecke | WUN-H2-E00-079 | CEILING | E3 0.1 m | 1116Dfl0000065404/03 | m² | Trockenbauarbeiten | 3 | 0.1 | 0 | 1 | Bekleidung | E3 | 0 | 0 | NEW | 2.5 | AllplanAttributes - Bezeichnung: Rasterdecke; ash_lichte Raumhöhe: (3400-36+764+100)/1000-0; Pset_CoveringCommon - FireRating: -; AcousticRating: -
Fliesen | WUN-H2-E00-079 | FLOORING | Fl1 0.2 m | 1116Bfl0000065405/01 | m² | Bodenbelagsarbeiten | 1 | 0.2 | 0 | 1 | Bodenfläche | Fl1 | 0 | 0 | NEW | AllplanAttributes - Bezeichnung: Fliesen; Raumnr. Bauherr: 2.11_A2_02; ash B_Aufbau: B2; ash B_Rutschhemmung: R10
Gipsfaserplatten 2-lagig (BSK) | WUN-H2-E00-080 | CEILING | layer 0.036 m | 1116Dfl0000065389/01 | m² | Trockenbauarbeiten | 1 | 0.036 | 0 | 1 | Deckenfläche |  | 0 | 0 | NEW | 2.5 | AllplanAttributes - Bezeichnung: Gipsfaserplatten 2-lagig (BSK)
Gipsfaserplatten 2-lagig (BSK) | WUN-H2-E00-080 | CEILING | Installationshöhe 0.764 m | 1116Dfl0000065389/02 | m² | Trockenbauarbeiten | 2 | 0.764 | 0 | 1 | Bekleidung | Installationshöhe | 0 | 0 | NEW | 2.5 | Pset_CoveringCommon - FireRating: für korrekte FläVisu; AllplanAttributes - ash_lichte Raumhöhe: (3400-36+764+100)/1000-0
Rasterdecke | WUN-H2-E00-080 | CEILING | E3 0.1 m | 1116Dfl0000065389/03 | m² | Trockenbauarbeiten | 3 | 0.1 | 0 | 1 | Bekleidung | E3 | 0 | 0 | NEW | 2.5 | AllplanAttributes - Bezeichnung: Rasterdecke; ash_lichte Raumhöhe: (3400-36+764+100)/1000-0; Pset_CoveringCommon - FireRating: -; AcousticRating: -
Fliesen | WUN-H2-E00-080 | FLOORING | Fl1 0.2 m | 1116Bfl0000065390/01 | m² | Bodenbelagsarbeiten | 1 | 0.2 | 0 | 1 | Bodenfläche | Fl1 | 0 | 0 | NEW | AllplanAttributes - Bezeichnung: Fliesen; Raumnr. Bauherr: 2.11_A2_02; ash B_Aufbau: B2; ash B_Rutschhemmung: R10
Fliesen | WUN-H2-E00-096a | FLOORING | Fl1 0.2 m | 1116Bfl0000066480/01 | m² | Bodenbelagsarbeiten | 1 | 0.2 | 0 | 1 | Bodenfläche | Fl1 | 0 | 0 | NEW | AllplanAttributes - Bezeichnung: Fliesen; Raumnr. Bauherr: 2.11_A2_02; ash B_Aufbau: B2; ash B_Rutschhemmung: R10
Fliesen Mosaik | WUN-H2-E00-096a | FLOORING | Fl2 0.2 m | 1116Bfl0001185726/01 | m² | Bodenbelagsarbeiten | 1 | 0.2 | 0 | 1 | Bodenfläche | Fl2 | 0 | 0 | NEW | AllplanAttributes - Bezeichnung: Fliesen Mosaik; Raumnr. Bauherr: 2.11_A2_02; ash B_Aufbau: B3; ash B_Rutschhemmung: R10; ash B_Bewertungsgruppe Barfußbereich: B
Gipsfaserplatten 2-lagig (BSK) | WUN-H2-E00-096a | CEILING | layer 0.036 m | 1116Dfl0000066481/01 | m² | Trockenbauarbeiten | 1 | 0.036 | 0 | 1 | Deckenfläche |  | 0 | 0 | NEW | 2.5 | AllplanAttributes - Bezeichnung: Gipsfaserplatten 2-lagig (BSK)
Gipsfaserplatten 2-lagig (BSK) | WUN-H2-E00-096a | CEILING | Installationshöhe 0.764 m | 1116Dfl0000066481/02 | m² | Trockenbauarbeiten | 2 | 0.764 | 0 | 1 | Bekleidung | Installationshöhe | 0 | 0 | NEW | 2.5 | Pset_CoveringCommon - FireRating: für korrekte FläVisu; AllplanAttributes - ash_lichte Raumhöhe: 2.500000; OKFF: 0
Gipskarton, imprägniert | WUN-H2-E00-096a | CEILING | B 0.1 m | 1116Dfl0000066481/03 | m² | Trockenbauarbeiten | 3 | 0.1 | 0 | 1 | Bekleidung | B | 0 | 0 | NEW | 2.5 | AllplanAttributes - Bezeichnung: Gipskarton, imprägniert; ash_lichte Raumhöhe: 2.500000; OKFF: 0; Pset_CoveringCommon - FireRating: -; AcousticRating: -
Gipsfaserplatten 2-lagig (BSK) | WUN-H2-E00-096a | CEILING | D1 0.001 m | 1116Dfl0000066481/04 | m² | Maler- und Lackierarbeiten | 4 | 0.001 | 0 | 1 | Bekleidung | D1 | 0 | 0 | NEW | 2.5 | AllplanAttributes - ash_lichte Raumhöhe: 2.500000; OKFF: 0
Gipsfaserplatten 2-lagig (BSK) | WUN-H2-E00-030 | CEILING | layer 0.036 m | 1116Dfl0000065393/01 | m² | Trockenbauarbeiten | 1 | 0.036 | 0 | 1 | Deckenfläche |  | 0 | 0 | NEW | 2.5 | AllplanAttributes - Bezeichnung: Gipsfaserplatten 2-lagig (BSK)
Gipsfaserplatten 2-lagig (BSK) | WUN-H2-E00-030 | CEILING | Installationshöhe 0.764 m | 1116Dfl0000065393/02 | m² | Trockenbauarbeiten | 2 | 0.764 | 0 | 1 | Bekleidung | Installationshöhe | 0 | 0 | NEW | 2.5 | Pset_CoveringCommon - FireRating: für korrekte FläVisu; AllplanAttributes - ash_lichte Raumhöhe: (3400-36+764+100)/1000-0
Rasterdecke | WUN-H2-E00-030 | CEILING | E3 0.1 m | 1116Dfl0000065393/03 | m² | Trockenbauarbeiten | 3 | 0.1 | 0 | 1 | Bekleidung | E3 | 0 | 0 | NEW | 2.5 | AllplanAttributes - Bezeichnung: Rasterdecke; ash_lichte Raumhöhe: (3400-36+764+100)/1000-0; Pset_CoveringCommon - FireRating: -; AcousticRating: -
Fliesen | WUN-H2-E00-030 | FLOORING | Fl1 0.2 m | 1116Bfl0000065392/01 | m² | Bodenbelagsarbeiten | 1 | 0.2 | 0 | 1 | Bodenfläche | Fl1 | 0 | 0 | NEW | AllplanAttributes - Bezeichnung: Fliesen; Raumnr. Bauherr: 2.11_A2_02; ash B_Aufbau: B2; ash B_Rutschhemmung: R10
PVC Bahnenware Holzoptik | WUN-H2-E00-063 | FLOORING | Ku1 0.2 m | 1116Bfl0000066598/01 | m² | Bodenbelagsarbeiten | 1 | 0.2 | 0 | 1 | Bodenfläche | Ku1 | 0 | 0 | NEW | AllplanAttributes - Bezeichnung: PVC Bahnenware Holzoptik; Raumnr. Bauherr: 2.11_A2_02; ash B_Aufbau: B1; ash B_Rutschhemmung: R9
Gipsfaserplatten 2-lagig (BSK) | WUN-H2-E00-063 | CEILING | layer 0.036 m | 1116Dfl0000443225/01 | m² | Trockenbauarbeiten | 1 | 0.036 | 0 | 1 | Deckenfläche |  | 0 | 0 | NEW | 2.5 | AllplanAttributes - Bezeichnung: Gipsfaserplatten 2-lagig (BSK)
Gipsfaserplatten 2-lagig (BSK) | WUN-H2-E00-063 | CEILING | Installationshöhe 0.714 m | 1116Dfl0000443225/02 | m² | Trockenbauarbeiten | 2 | 0.714 | 0 | 1 | Bekleidung | Installationshöhe | 0 | 0 | NEW | 2.5 | Pset_CoveringCommon - FireRating: für korrekte FläVisu; AllplanAttributes - ash_lichte Raumhöhe: 2.500000
Gipsfaserplatten 2-lagig (BSK) | WUN-H2-E00-063 | CEILING | Aa 0.15 m | 1116Dfl0000443225/03 | m² | Trockenbauarbeiten | 3 | 0.15 | 0 | 1 | Bekleidung | Aa | 0 | 0 | NEW | 2.5 | AllplanAttributes - ash_lichte Raumhöhe: 2.500000; Pset_CoveringCommon - AcousticRating: -
Gipsfaserplatten 2-lagig (BSK) | WUN-H2-E00-063 | CEILING | D1 0.001 m | 1116Dfl0000443225/04 | m² | Maler- und Lackierarbeiten | 4 | 0.001 | 0 | 1 | Bekleidung | D1 | 0 | 0 | NEW | 2.5 | AllplanAttributes - ash_lichte Raumhöhe: 2.500000
Gipsfaserplatten 2-lagig (BSK) | WUN-H2-E00-063 | CEILING | layer 0.036 m | 1116Dfl0000066597/01 | m² | Trockenbauarbeiten | 1 | 0.036 | 0 | 1 | Deckenfläche |  | 0 | 0 | NEW | 2.5 | AllplanAttributes - Bezeichnung: Gipsfaserplatten 2-lagig (BSK)
Gipsfaserplatten 2-lagig (BSK) | WUN-H2-E00-063 | CEILING | Installationshöhe 0.714 m | 1116Dfl0000066597/02 | m² | Trockenbauarbeiten | 2 | 0.714 | 0 | 1 | Bekleidung | Installationshöhe | 0 | 0 | NEW | 2.5 | Pset_CoveringCommon - FireRating: für korrekte FläVisu; AllplanAttributes - ash_lichte Raumhöhe: 2.500000; OKFF: 0
Gipsfaserplatten 2-lagig (BSK) | WUN-H2-E00-063 | CEILING | A1 0.15 m | 1116Dfl0000066597/03 | m² | Trockenbauarbeiten | 3 | 0.15 | 0 | 1 | Bekleidung | A1 | 0 | 0 | NEW | 2.5 | Pset_CoveringCommon - FireRating: -; AcousticRating: -; AllplanAttributes - ash_lichte Raumhöhe: 2.500000; OKFF: 0
Gipsfaserplatten 2-lagig (BSK) | WUN-H2-E00-063 | CEILING | D1 0.001 m | 1116Dfl0000066597/04 | m² | Maler- und Lackierarbeiten | 4 | 0.001 | 0 | 1 | Bekleidung | D1 | 0 | 0 | NEW | 2.5 | AllplanAttributes - ash_lichte Raumhöhe: 2.500000; OKFF: 0
PVC Bahnenware Holzoptik | WUN-H2-E00-F03a | FLOORING | Ku1 0.2 m | 1116Bfl0000227272/01 | m² | Bodenbelagsarbeiten | 1 | 0.2 | 0 | 1 | Bodenfläche | Ku1 | 0 | 0 | NEW | AllplanAttributes - Bezeichnung: PVC Bahnenware Holzoptik; Raumnr. Bauherr: 2.11_A2_02; ash B_Aufbau: B1; ash B_Rutschhemmung: R9
Gipsfaserplatten 2-lagig (BSK) | WUN-H2-E00-F03a | CEILING | layer 0.036 m | 1116Dfl0000227271/01 | m² | Trockenbauarbeiten | 1 | 0.036 | 0 | 1 | Deckenfläche |  | 0 | 0 | NEW | 2.5 | AllplanAttributes - Bezeichnung: Gipsfaserplatten 2-lagig (BSK)
Gipsfaserplatten 2-lagig (BSK) | WUN-H2-E00-F03a | CEILING | Installationshöhe 0.714 m | 1116Dfl0000227271/02 | m² | Trockenbauarbeiten | 2 | 0.714 | 0 | 1 | Bekleidung | Installationshöhe | 0 | 0 | NEW | 2.5 | Pset_CoveringCommon - FireRating: für korrekte FläVisu; AllplanAttributes - ash_lichte Raumhöhe: 2.500000
Gipsfaserplatten 2-lagig (BSK) | WUN-H2-E00-F03a | CEILING | A1 0.15 m | 1116Dfl0000227271/03 | m² | Trockenbauarbeiten | 3 | 0.15 | 0 | 1 | Bekleidung | A1 | 0 | 0 | NEW | 2.5 | Pset_CoveringCommon - FireRating: -; AcousticRating: -; AllplanAttributes - ash_lichte Raumhöhe: 2.500000
Gipsfaserplatten 2-lagig (BSK) | WUN-H2-E00-F03a | CEILING | D1 0.001 m | 1116Dfl0000227271/04 | m² | Maler- und Lackierarbeiten | 4 | 0.001 | 0 | 1 | Bekleidung | D1 | 0 | 0 | NEW | 2.5 | AllplanAttributes - ash_lichte Raumhöhe: 2.500000
Gipsfaserplatten 2-lagig (BSK) | WUN-H2-E00-F03a | CEILING | layer 0.036 m | 1116Dfl0000436150/01 | m² | Trockenbauarbeiten | 1 | 0.036 | 0 | 1 | Deckenfläche |  | 0 | 0 | NEW | 2.5 | AllplanAttributes - Bezeichnung: Gipsfaserplatten 2-lagig (BSK)
Gipsfaserplatten 2-lagig (BSK) | WUN-H2-E00-F03a | CEILING | Installationshöhe 0.714 m | 1116Dfl0000436150/02 | m² | Trockenbauarbeiten | 2 | 0.714 | 0 | 1 | Bekleidung | Installationshöhe | 0 | 0 | NEW | 2.5 | Pset_CoveringCommon - FireRating: für korrekte FläVisu; AllplanAttributes - ash_lichte Raumhöhe: 2.500000; OKFF: 0
Gipsfaserplatten 2-lagig (BSK) | WUN-H2-E00-F03a | CEILING | Aa 0.15 m | 1116Dfl0000436150/03 | m² | Trockenbauarbeiten | 3 | 0.15 | 0 | 1 | Bekleidung | Aa | 0 | 0 | NEW | 2.5 | Pset_CoveringCommon - FireRating: -; AcousticRating: -; AllplanAttributes - ash_lichte Raumhöhe: 2.500000; OKFF: 0
Gipsfaserplatten 2-lagig (BSK) | WUN-H2-E00-F03a | CEILING | D1 0.001 m | 1116Dfl0000436150/04 | m² | Maler- und Lackierarbeiten | 4 | 0.001 | 0 | 1 | Bekleidung | D1 | 0 | 0 | NEW | 2.5 | AllplanAttributes - ash_lichte Raumhöhe: 2.500000; OKFF: 0
PVC Bahnenware Holzoptik | WUN-H2-E00-009 | FLOORING | Ku1 0.2 m | 1116Bfl0000066530/01 | m² | Bodenbelagsarbeiten | 1 | 0.2 | 0 | 1 | Bodenfläche | Ku1 | 0 | 0 | NEW | AllplanAttributes - Bezeichnung: PVC Bahnenware Holzoptik; Raumnr. Bauherr: 2.11_A2_02; ash B_Aufbau: B1; ash B_Rutschhemmung: R9
Gipsfaserplatten 2-lagig (BSK) | WUN-H2-E00-009 | CEILING | layer 0.036 m | 1116Dfl0000066529/01 | m² | Trockenbauarbeiten | 1 | 0.036 | 0 | 1 | Deckenfläche |  | 0 | 0 | NEW | 2.5 | AllplanAttributes - Bezeichnung: Gipsfaserplatten 2-lagig (BSK)
Gipsfaserplatten 2-lagig (BSK) | WUN-H2-E00-009 | CEILING | Installationshöhe 0.764 m | 1116Dfl0000066529/02 | m² | Trockenbauarbeiten | 2 | 0.764 | 0 | 1 | Bekleidung | Installationshöhe | 0 | 0 | NEW | 2.5 | Pset_CoveringCommon - FireRating: für korrekte FläVisu; AllplanAttributes - ash_lichte Raumhöhe: 2.500000; OKFF: 0
Kühldecke glatt | WUN-H2-E00-009 | CEILING | H7a 0.1 m | 1116Dfl0000066529/03 | m² | Trockenbauarbeiten | 3 | 0.1 | 0 | 1 | Bekleidung | H7a | 0 | 0 | NEW | 2.5 | AllplanAttributes - Bezeichnung: Kühldecke glatt; ash_lichte Raumhöhe: 2.500000; OKFF: 0; Pset_CoveringCommon - FireRating: -; AcousticRating: -
Gipsfaserplatten 2-lagig (BSK) | WUN-H2-E00-009 | CEILING | D1 0.001 m | 1116Dfl0000066529/04 | m² | Maler- und Lackierarbeiten | 4 | 0.001 | 0 | 1 | Bekleidung | D1 | 0 | 0 | NEW | 2.5 | AllplanAttributes - ash_lichte Raumhöhe: 2.500000; OKFF: 0
Gipsfaserplatten 2-lagig (BSK) | WUN-H2-E00-077 | CEILING | layer 0.036 m | 1116Dfl0000065627/01 | m² | Trockenbauarbeiten | 1 | 0.036 | 0 | 1 | Deckenfläche |  | 0 | 0 | NEW | 2.5 | AllplanAttributes - Bezeichnung: Gipsfaserplatten 2-lagig (BSK)
Gipsfaserplatten 2-lagig (BSK) | WUN-H2-E00-077 | CEILING | Installationshöhe 0.764 m | 1116Dfl0000065627/02 | m² | Trockenbauarbeiten | 2 | 0.764 | 0 | 1 | Bekleidung | Installationshöhe | 0 | 0 | NEW | 2.5 | Pset_CoveringCommon - FireRating: für korrekte FläVisu; AllplanAttributes - ash_lichte Raumhöhe: (3400-36+764+100)/1000-0
Rasterdecke | WUN-H2-E00-077 | CEILING | E3 0.1 m | 1116Dfl0000065627/03 | m² | Trockenbauarbeiten | 3 | 0.1 | 0 | 1 | Bekleidung | E3 | 0 | 0 | NEW | 2.5 | AllplanAttributes - Bezeichnung: Rasterdecke; ash_lichte Raumhöhe: (3400-36+764+100)/1000-0; Pset_CoveringCommon - FireRating: -; AcousticRating: -
PVC Bahnenware Uni | WUN-H2-E00-077 | FLOORING | Ku2 0.2 m | 1116Bfl0000065628/01 | m² | Bodenbelagsarbeiten | 1 | 0.2 | 0 | 1 | Bodenfläche | Ku2 | 0 | 0 | NEW | AllplanAttributes - Bezeichnung: PVC Bahnenware Uni; Raumnr. Bauherr: 2.11_A2_02; ash B_Aufbau: B1; ash B_Rutschhemmung: R9
PVC Bahnenware Holzoptik | WUN-H2-E00-049 | FLOORING | Ku1 0.2 m | 1116Bfl0000065335/01 | m² | Bodenbelagsarbeiten | 1 | 0.2 | 0 | 1 | Bodenfläche | Ku1 | 0 | 0 | NEW | AllplanAttributes - Bezeichnung: PVC Bahnenware Holzoptik; Raumnr. Bauherr: 2.11_A2_02; ash B_Aufbau: B1; ash B_Rutschhemmung: R9
Gipsfaserplatten 2-lagig (BSK) | WUN-H2-E00-049 | CEILING | layer 0.036 m | 1116Dfl0000065334/01 | m² | Trockenbauarbeiten | 1 | 0.036 | 0 | 1 | Deckenfläche |  | 0 | 0 | NEW | 2.5 | AllplanAttributes - Bezeichnung: Gipsfaserplatten 2-lagig (BSK)
Gipsfaserplatten 2-lagig (BSK) | WUN-H2-E00-049 | CEILING | Installationshöhe 0.764 m | 1116Dfl0000065334/02 | m² | Trockenbauarbeiten | 2 | 0.764 | 0 | 1 | Bekleidung | Installationshöhe | 0 | 0 | NEW | 2.5 | Pset_CoveringCommon - FireRating: für korrekte FläVisu; AllplanAttributes - ash_lichte Raumhöhe: 2.500000; OKFF: 0
Gipskarton, imprägniert | WUN-H2-E00-049 | CEILING | B 0.1 m | 1116Dfl0000065334/03 | m² | Trockenbauarbeiten | 3 | 0.1 | 0 | 1 | Bekleidung | B | 0 | 0 | NEW | 2.5 | AllplanAttributes - Bezeichnung: Gipskarton, imprägniert; ash_lichte Raumhöhe: 2.500000; OKFF: 0; Pset_CoveringCommon - FireRating: -; AcousticRating: -
Gipsfaserplatten 2-lagig (BSK) | WUN-H2-E00-049 | CEILING | D1 0.001 m | 1116Dfl0000065334/04 | m² | Maler- und Lackierarbeiten | 4 | 0.001 | 0 | 1 | Bekleidung | D1 | 0 | 0 | NEW | 2.5 | AllplanAttributes - ash_lichte Raumhöhe: 2.500000; OKFF: 0
Gipsfaserplatten 2-lagig (BSK) | WUN-H2-E00-078 | CEILING | layer 0.036 m | 1116Dfl0000065622/01 | m² | Trockenbauarbeiten | 1 | 0.036 | 0 | 1 | Deckenfläche |  | 0 | 0 | NEW | 2.5 | AllplanAttributes - Bezeichnung: Gipsfaserplatten 2-lagig (BSK)
Gipsfaserplatten 2-lagig (BSK) | WUN-H2-E00-078 | CEILING | Installationshöhe 0.764 m | 1116Dfl0000065622/02 | m² | Trockenbauarbeiten | 2 | 0.764 | 0 | 1 | Bekleidung | Installationshöhe | 0 | 0 | NEW | 2.5 | Pset_CoveringCommon - FireRating: für korrekte FläVisu; AllplanAttributes - ash_lichte Raumhöhe: (3400-36+764+100)/1000-0
Rasterdecke | WUN-H2-E00-078 | CEILING | E3 0.1 m | 1116Dfl0000065622/03 | m² | Trockenbauarbeiten | 3 | 0.1 | 0 | 1 | Bekleidung | E3 | 0 | 0 | NEW | 2.5 | AllplanAttributes - Bezeichnung: Rasterdecke; ash_lichte Raumhöhe: (3400-36+764+100)/1000-0; Pset_CoveringCommon - FireRating: -; AcousticRating: -
PVC Bahnenware Uni | WUN-H2-E00-078 | FLOORING | Ku2 0.2 m | 1116Bfl0000065623/01 | m² | Bodenbelagsarbeiten | 1 | 0.2 | 0 | 1 | Bodenfläche | Ku2 | 0 | 0 | NEW | AllplanAttributes - Bezeichnung: PVC Bahnenware Uni; Raumnr. Bauherr: 2.11_A2_02; ash B_Aufbau: B1; ash B_Rutschhemmung: R9
Fliesen | WUN-H2-E00-019a | FLOORING | Fl1 0.2 m | 1116Bfl0000066372/01 | m² | Bodenbelagsarbeiten | 1 | 0.2 | 0 | 1 | Bodenfläche | Fl1 | 0 | 0 | NEW | AllplanAttributes - Bezeichnung: Fliesen; Raumnr. Bauherr: 2.11_A2_02; ash B_Aufbau: B2; ash B_Rutschhemmung: R10
Fliesen Mosaik | WUN-H2-E00-019a | FLOORING | Fl2 0.2 m | 1116Bfl0001165200/01 | m² | Bodenbelagsarbeiten | 1 | 0.2 | 0 | 1 | Bodenfläche | Fl2 | 0 | 0 | NEW | AllplanAttributes - Bezeichnung: Fliesen Mosaik; Raumnr. Bauherr: 2.11_A2_02; ash B_Aufbau: B3; ash B_Rutschhemmung: R10; ash B_Bewertungsgruppe Barfußbereich: B
Gipsfaserplatten 2-lagig (BSK) | WUN-H2-E00-019a | CEILING | layer 0.036 m | 1116Dfl0000066373/01 | m² | Trockenbauarbeiten | 1 | 0.036 | 0 | 1 | Deckenfläche |  | 0 | 0 | NEW | 2.5 | AllplanAttributes - Bezeichnung: Gipsfaserplatten 2-lagig (BSK)
Gipsfaserplatten 2-lagig (BSK) | WUN-H2-E00-019a | CEILING | Installationshöhe 0.764 m | 1116Dfl0000066373/02 | m² | Trockenbauarbeiten | 2 | 0.764 | 0 | 1 | Bekleidung | Installationshöhe | 0 | 0 | NEW | 2.5 | Pset_CoveringCommon - FireRating: für korrekte FläVisu; AllplanAttributes - ash_lichte Raumhöhe: 2.500000; OKFF: 0
Gipskarton, imprägniert | WUN-H2-E00-019a | CEILING | B 0.1 m | 1116Dfl0000066373/03 | m² | Trockenbauarbeiten | 3 | 0.1 | 0 | 1 | Bekleidung | B | 0 | 0 | NEW | 2.5 | AllplanAttributes - Bezeichnung: Gipskarton, imprägniert; ash_lichte Raumhöhe: 2.500000; OKFF: 0; Pset_CoveringCommon - FireRating: -; AcousticRating: -
Gipsfaserplatten 2-lagig (BSK) | WUN-H2-E00-019a | CEILING | D1 0.001 m | 1116Dfl0000066373/04 | m² | Maler- und Lackierarbeiten | 4 | 0.001 | 0 | 1 | Bekleidung | D1 | 0 | 0 | NEW | 2.5 | AllplanAttributes - ash_lichte Raumhöhe: 2.500000; OKFF: 0
 | WUN-H2-E00-047a | SKIRTINGBOARD |  | 1116Lei0000232050 | m |  |  |  |  | 1 | Leiste |  | 0 | 0 | NEW
Fliesen | WUN-H2-E00-047a | FLOORING | Fl1 0.2 m | 1116Bfl0000065568/01 | m² | Bodenbelagsarbeiten | 1 | 0.2 | 0 | 1 | Bodenfläche | Fl1 | 0 | 0 | NEW | AllplanAttributes - Bezeichnung: Fliesen; Raumnr. Bauherr: 2.11_A2_02; ash B_Aufbau: B2; ash B_Rutschhemmung: R10
Fliesen Mosaik | WUN-H2-E00-047a | FLOORING | Fl2 0.2 m | 1116Bfl0001166813/01 | m² | Bodenbelagsarbeiten | 1 | 0.2 | 0 | 1 | Bodenfläche | Fl2 | 0 | 0 | NEW | AllplanAttributes - Bezeichnung: Fliesen Mosaik; Raumnr. Bauherr: 2.11_A2_02; ash B_Aufbau: B3; ash B_Rutschhemmung: R10; ash B_Bewertungsgruppe Barfußbereich: B
Gipsfaserplatten 2-lagig (BSK) | WUN-H2-E00-047a | CEILING | layer 0.036 m | 1116Dfl0000065569/01 | m² | Trockenbauarbeiten | 1 | 0.036 | 0 | 1 | Deckenfläche |  | 0 | 0 | NEW | 2.5 | AllplanAttributes - Bezeichnung: Gipsfaserplatten 2-lagig (BSK)
Gipsfaserplatten 2-lagig (BSK) | WUN-H2-E00-047a | CEILING | Installationshöhe 0.764 m | 1116Dfl0000065569/02 | m² | Trockenbauarbeiten | 2 | 0.764 | 0 | 1 | Bekleidung | Installationshöhe | 0 | 0 | NEW | 2.5 | Pset_CoveringCommon - FireRating: für korrekte FläVisu; AllplanAttributes - ash_lichte Raumhöhe: 2.500000; OKFF: 0
Gipskarton, imprägniert | WUN-H2-E00-047a | CEILING | B 0.1 m | 1116Dfl0000065569/03 | m² | Trockenbauarbeiten | 3 | 0.1 | 0 | 1 | Bekleidung | B | 0 | 0 | NEW | 2.5 | AllplanAttributes - Bezeichnung: Gipskarton, imprägniert; ash_lichte Raumhöhe: 2.500000; OKFF: 0; Pset_CoveringCommon - FireRating: -; AcousticRating: -
Gipsfaserplatten 2-lagig (BSK) | WUN-H2-E00-047a | CEILING | D1 0.001 m | 1116Dfl0000065569/04 | m² | Maler- und Lackierarbeiten | 4 | 0.001 | 0 | 1 | Bekleidung | D1 | 0 | 0 | NEW | 2.5 | AllplanAttributes - ash_lichte Raumhöhe: 2.500000; OKFF: 0
 | WUN-H2-E00-045a | SKIRTINGBOARD |  | 1116Lei0000232048 | m |  |  |  |  | 1 | Leiste |  | 0 | 0 | NEW
Fliesen | WUN-H2-E00-045a | FLOORING | Fl1 0.2 m | 1116Bfl0000065222/01 | m² | Bodenbelagsarbeiten | 1 | 0.2 | 0 | 1 | Bodenfläche | Fl1 | 0 | 0 | NEW | AllplanAttributes - Bezeichnung: Fliesen; Raumnr. Bauherr: 2.11_A2_02; ash B_Aufbau: B2; ash B_Rutschhemmung: R10
Fliesen Mosaik | WUN-H2-E00-045a | FLOORING | Fl2 0.2 m | 1116Bfl0001166413/01 | m² | Bodenbelagsarbeiten | 1 | 0.2 | 0 | 1 | Bodenfläche | Fl2 | 0 | 0 | NEW | AllplanAttributes - Bezeichnung: Fliesen Mosaik; Raumnr. Bauherr: 2.11_A2_02; ash B_Aufbau: B3; ash B_Rutschhemmung: R10; ash B_Bewertungsgruppe Barfußbereich: B
Gipsfaserplatten 2-lagig (BSK) | WUN-H2-E00-045a | CEILING | layer 0.036 m | 1116Dfl0000065223/01 | m² | Trockenbauarbeiten | 1 | 0.036 | 0 | 1 | Deckenfläche |  | 0 | 0 | NEW | 2.5 | AllplanAttributes - Bezeichnung: Gipsfaserplatten 2-lagig (BSK)
Gipsfaserplatten 2-lagig (BSK) | WUN-H2-E00-045a | CEILING | Installationshöhe 0.764 m | 1116Dfl0000065223/02 | m² | Trockenbauarbeiten | 2 | 0.764 | 0 | 1 | Bekleidung | Installationshöhe | 0 | 0 | NEW | 2.5 | Pset_CoveringCommon - FireRating: für korrekte FläVisu; AllplanAttributes - ash_lichte Raumhöhe: 2.500000; OKFF: 0
Gipskarton, imprägniert | WUN-H2-E00-045a | CEILING | B 0.1 m | 1116Dfl0000065223/03 | m² | Trockenbauarbeiten | 3 | 0.1 | 0 | 1 | Bekleidung | B | 0 | 0 | NEW | 2.5 | AllplanAttributes - Bezeichnung: Gipskarton, imprägniert; ash_lichte Raumhöhe: 2.500000; OKFF: 0; Pset_CoveringCommon - FireRating: -; AcousticRating: -
Gipsfaserplatten 2-lagig (BSK) | WUN-H2-E00-045a | CEILING | D1 0.001 m | 1116Dfl0000065223/04 | m² | Maler- und Lackierarbeiten | 4 | 0.001 | 0 | 1 | Bekleidung | D1 | 0 | 0 | NEW | 2.5 | AllplanAttributes - ash_lichte Raumhöhe: 2.500000; OKFF: 0
 | WUN-H2-E00-044a | SKIRTINGBOARD |  | 1116Lei0000232047 | m |  |  |  |  | 1 | Leiste |  | 0 | 0 | NEW
Fliesen | WUN-H2-E00-044a | FLOORING | Fl1 0.2 m | 1116Bfl0000065230/01 | m² | Bodenbelagsarbeiten | 1 | 0.2 | 0 | 1 | Bodenfläche | Fl1 | 0 | 0 | NEW | AllplanAttributes - Bezeichnung: Fliesen; Raumnr. Bauherr: 2.11_A2_02; ash B_Aufbau: B2; ash B_Rutschhemmung: R10
Fliesen Mosaik | WUN-H2-E00-044a | FLOORING | Fl2 0.2 m | 1116Bfl0001166211/01 | m² | Bodenbelagsarbeiten | 1 | 0.2 | 0 | 1 | Bodenfläche | Fl2 | 0 | 0 | NEW | AllplanAttributes - Bezeichnung: Fliesen Mosaik; Raumnr. Bauherr: 2.11_A2_02; ash B_Aufbau: B3; ash B_Rutschhemmung: R10; ash B_Bewertungsgruppe Barfußbereich: B
Gipsfaserplatten 2-lagig (BSK) | WUN-H2-E00-044a | CEILING | layer 0.036 m | 1116Dfl0000065231/01 | m² | Trockenbauarbeiten | 1 | 0.036 | 0 | 1 | Deckenfläche |  | 0 | 0 | NEW | 2.5 | AllplanAttributes - Bezeichnung: Gipsfaserplatten 2-lagig (BSK)
Gipsfaserplatten 2-lagig (BSK) | WUN-H2-E00-044a | CEILING | Installationshöhe 0.764 m | 1116Dfl0000065231/02 | m² | Trockenbauarbeiten | 2 | 0.764 | 0 | 1 | Bekleidung | Installationshöhe | 0 | 0 | NEW | 2.5 | Pset_CoveringCommon - FireRating: für korrekte FläVisu; AllplanAttributes - ash_lichte Raumhöhe: 2.500000; OKFF: 0
Gipskarton, imprägniert | WUN-H2-E00-044a | CEILING | B 0.1 m | 1116Dfl0000065231/03 | m² | Trockenbauarbeiten | 3 | 0.1 | 0 | 1 | Bekleidung | B | 0 | 0 | NEW | 2.5 | AllplanAttributes - Bezeichnung: Gipskarton, imprägniert; ash_lichte Raumhöhe: 2.500000; OKFF: 0; Pset_CoveringCommon - FireRating: -; AcousticRating: -
Gipsfaserplatten 2-lagig (BSK) | WUN-H2-E00-044a | CEILING | D1 0.001 m | 1116Dfl0000065231/04 | m² | Maler- und Lackierarbeiten | 4 | 0.001 | 0 | 1 | Bekleidung | D1 | 0 | 0 | NEW | 2.5 | AllplanAttributes - ash_lichte Raumhöhe: 2.500000; OKFF: 0
 | WUN-H2-E00-043a | SKIRTINGBOARD |  | 1116Lei0000232019 | m |  |  |  |  | 1 | Leiste |  | 0 | 0 | NEW
Fliesen | WUN-H2-E00-043a | FLOORING | Fl1 0.2 m | 1116Bfl0000065220/01 | m² | Bodenbelagsarbeiten | 1 | 0.2 | 0 | 1 | Bodenfläche | Fl1 | 0 | 0 | NEW | AllplanAttributes - Bezeichnung: Fliesen; Raumnr. Bauherr: 2.11_A2_02; ash B_Aufbau: B2; ash B_Rutschhemmung: R10
Fliesen Mosaik | WUN-H2-E00-043a | FLOORING | Fl2 0.2 m | 1116Bfl0001166011/01 | m² | Bodenbelagsarbeiten | 1 | 0.2 | 0 | 1 | Bodenfläche | Fl2 | 0 | 0 | NEW | AllplanAttributes - Bezeichnung: Fliesen Mosaik; Raumnr. Bauherr: 2.11_A2_02; ash B_Aufbau: B3; ash B_Rutschhemmung: R10; ash B_Bewertungsgruppe Barfußbereich: B
Gipsfaserplatten 2-lagig (BSK) | WUN-H2-E00-043a | CEILING | layer 0.036 m | 1116Dfl0000065221/01 | m² | Trockenbauarbeiten | 1 | 0.036 | 0 | 1 | Deckenfläche |  | 0 | 0 | NEW | 2.5 | AllplanAttributes - Bezeichnung: Gipsfaserplatten 2-lagig (BSK)
Gipsfaserplatten 2-lagig (BSK) | WUN-H2-E00-043a | CEILING | Installationshöhe 0.764 m | 1116Dfl0000065221/02 | m² | Trockenbauarbeiten | 2 | 0.764 | 0 | 1 | Bekleidung | Installationshöhe | 0 | 0 | NEW | 2.5 | Pset_CoveringCommon - FireRating: für korrekte FläVisu; AllplanAttributes - ash_lichte Raumhöhe: 2.500000; OKFF: 0
Gipskarton, imprägniert | WUN-H2-E00-043a | CEILING | B 0.1 m | 1116Dfl0000065221/03 | m² | Trockenbauarbeiten | 3 | 0.1 | 0 | 1 | Bekleidung | B | 0 | 0 | NEW | 2.5 | AllplanAttributes - Bezeichnung: Gipskarton, imprägniert; ash_lichte Raumhöhe: 2.500000; OKFF: 0; Pset_CoveringCommon - FireRating: -; AcousticRating: -
Gipsfaserplatten 2-lagig (BSK) | WUN-H2-E00-043a | CEILING | D1 0.001 m | 1116Dfl0000065221/04 | m² | Maler- und Lackierarbeiten | 4 | 0.001 | 0 | 1 | Bekleidung | D1 | 0 | 0 | NEW | 2.5 | AllplanAttributes - ash_lichte Raumhöhe: 2.500000; OKFF: 0
Fliesen | WUN-H2-E00-090a | FLOORING | Fl1 0.2 m | 1116Bfl0000065264/01 | m² | Bodenbelagsarbeiten | 1 | 0.2 | 0 | 1 | Bodenfläche | Fl1 | 0 | 0 | NEW | AllplanAttributes - Bezeichnung: Fliesen; Raumnr. Bauherr: 2.11_A2_02; ash B_Aufbau: B2; ash B_Rutschhemmung: R10
Fliesen Mosaik | WUN-H2-E00-090a | FLOORING | Fl2 0.2 m | 1116Bfl0001168526/01 | m² | Bodenbelagsarbeiten | 1 | 0.2 | 0 | 1 | Bodenfläche | Fl2 | 0 | 0 | NEW | AllplanAttributes - Bezeichnung: Fliesen Mosaik; Raumnr. Bauherr: 2.11_A2_02; ash B_Aufbau: B3; ash B_Rutschhemmung: R10; ash B_Bewertungsgruppe Barfußbereich: B
Gipsfaserplatten 2-lagig (BSK) | WUN-H2-E00-090a | CEILING | layer 0.036 m | 1116Dfl0000065265/01 | m² | Trockenbauarbeiten | 1 | 0.036 | 0 | 1 | Deckenfläche |  | 0 | 0 | NEW | 2.5 | AllplanAttributes - Bezeichnung: Gipsfaserplatten 2-lagig (BSK)
Gipsfaserplatten 2-lagig (BSK) | WUN-H2-E00-090a | CEILING | Installationshöhe 0.764 m | 1116Dfl0000065265/02 | m² | Trockenbauarbeiten | 2 | 0.764 | 0 | 1 | Bekleidung | Installationshöhe | 0 | 0 | NEW | 2.5 | Pset_CoveringCommon - FireRating: für korrekte FläVisu; AllplanAttributes - ash_lichte Raumhöhe: 2.500000; OKFF: 0
Gipskarton, imprägniert | WUN-H2-E00-090a | CEILING | B 0.1 m | 1116Dfl0000065265/03 | m² | Trockenbauarbeiten | 3 | 0.1 | 0 | 1 | Bekleidung | B | 0 | 0 | NEW | 2.5 | AllplanAttributes - Bezeichnung: Gipskarton, imprägniert; ash_lichte Raumhöhe: 2.500000; OKFF: 0; Pset_CoveringCommon - FireRating: -; AcousticRating: -
Gipsfaserplatten 2-lagig (BSK) | WUN-H2-E00-090a | CEILING | D1 0.001 m | 1116Dfl0000065265/04 | m² | Maler- und Lackierarbeiten | 4 | 0.001 | 0 | 1 | Bekleidung | D1 | 0 | 0 | NEW | 2.5 | AllplanAttributes - ash_lichte Raumhöhe: 2.500000; OKFF: 0
Fliesen | WUN-H2-E00-092a | FLOORING | Fl1 0.2 m | 1116Bfl0000065260/01 | m² | Bodenbelagsarbeiten | 1 | 0.2 | 0 | 1 | Bodenfläche | Fl1 | 0 | 0 | NEW | AllplanAttributes - Bezeichnung: Fliesen; Raumnr. Bauherr: 2.11_A2_02; ash B_Aufbau: B2; ash B_Rutschhemmung: R10
Fliesen Mosaik | WUN-H2-E00-092a | FLOORING | Fl2 0.2 m | 1116Bfl0001169028/01 | m² | Bodenbelagsarbeiten | 1 | 0.2 | 0 | 1 | Bodenfläche | Fl2 | 0 | 0 | NEW | AllplanAttributes - Bezeichnung: Fliesen Mosaik; Raumnr. Bauherr: 2.11_A2_02; ash B_Aufbau: B3; ash B_Rutschhemmung: R10; ash B_Bewertungsgruppe Barfußbereich: B
Gipsfaserplatten 2-lagig (BSK) | WUN-H2-E00-092a | CEILING | layer 0.036 m | 1116Dfl0000065261/01 | m² | Trockenbauarbeiten | 1 | 0.036 | 0 | 1 | Deckenfläche |  | 0 | 0 | NEW | 2.5 | AllplanAttributes - Bezeichnung: Gipsfaserplatten 2-lagig (BSK)
Gipsfaserplatten 2-lagig (BSK) | WUN-H2-E00-092a | CEILING | Installationshöhe 0.764 m | 1116Dfl0000065261/02 | m² | Trockenbauarbeiten | 2 | 0.764 | 0 | 1 | Bekleidung | Installationshöhe | 0 | 0 | NEW | 2.5 | Pset_CoveringCommon - FireRating: für korrekte FläVisu; AllplanAttributes - ash_lichte Raumhöhe: 2.500000; OKFF: 0
Gipskarton, imprägniert | WUN-H2-E00-092a | CEILING | B 0.1 m | 1116Dfl0000065261/03 | m² | Trockenbauarbeiten | 3 | 0.1 | 0 | 1 | Bekleidung | B | 0 | 0 | NEW | 2.5 | AllplanAttributes - Bezeichnung: Gipskarton, imprägniert; ash_lichte Raumhöhe: 2.500000; OKFF: 0; Pset_CoveringCommon - FireRating: -; AcousticRating: -
Gipsfaserplatten 2-lagig (BSK) | WUN-H2-E00-092a | CEILING | D1 0.001 m | 1116Dfl0000065261/04 | m² | Maler- und Lackierarbeiten | 4 | 0.001 | 0 | 1 | Bekleidung | D1 | 0 | 0 | NEW | 2.5 | AllplanAttributes - ash_lichte Raumhöhe: 2.500000; OKFF: 0
Fliesen | WUN-H2-E00-093a | FLOORING | Fl1 0.2 m | 1116Bfl0000065258/01 | m² | Bodenbelagsarbeiten | 1 | 0.2 | 0 | 1 | Bodenfläche | Fl1 | 0 | 0 | NEW | AllplanAttributes - Bezeichnung: Fliesen; Raumnr. Bauherr: 2.11_A2_02; ash B_Aufbau: B2; ash B_Rutschhemmung: R10
Fliesen Mosaik | WUN-H2-E00-093a | FLOORING | Fl2 0.2 m | 1116Bfl0001169228/01 | m² | Bodenbelagsarbeiten | 1 | 0.2 | 0 | 1 | Bodenfläche | Fl2 | 0 | 0 | NEW | AllplanAttributes - Bezeichnung: Fliesen Mosaik; Raumnr. Bauherr: 2.11_A2_02; ash B_Aufbau: B3; ash B_Rutschhemmung: R10; ash B_Bewertungsgruppe Barfußbereich: B
Gipsfaserplatten 2-lagig (BSK) | WUN-H2-E00-093a | CEILING | layer 0.036 m | 1116Dfl0000065259/01 | m² | Trockenbauarbeiten | 1 | 0.036 | 0 | 1 | Deckenfläche |  | 0 | 0 | NEW | 2.5 | AllplanAttributes - Bezeichnung: Gipsfaserplatten 2-lagig (BSK)
Gipsfaserplatten 2-lagig (BSK) | WUN-H2-E00-093a | CEILING | Installationshöhe 0.764 m | 1116Dfl0000065259/02 | m² | Trockenbauarbeiten | 2 | 0.764 | 0 | 1 | Bekleidung | Installationshöhe | 0 | 0 | NEW | 2.5 | Pset_CoveringCommon - FireRating: für korrekte FläVisu; AllplanAttributes - ash_lichte Raumhöhe: 2.500000; OKFF: 0
Gipskarton, imprägniert | WUN-H2-E00-093a | CEILING | B 0.1 m | 1116Dfl0000065259/03 | m² | Trockenbauarbeiten | 3 | 0.1 | 0 | 1 | Bekleidung | B | 0 | 0 | NEW | 2.5 | AllplanAttributes - Bezeichnung: Gipskarton, imprägniert; ash_lichte Raumhöhe: 2.500000; OKFF: 0; Pset_CoveringCommon - FireRating: -; AcousticRating: -
Gipsfaserplatten 2-lagig (BSK) | WUN-H2-E00-093a | CEILING | D1 0.001 m | 1116Dfl0000065259/04 | m² | Maler- und Lackierarbeiten | 4 | 0.001 | 0 | 1 | Bekleidung | D1 | 0 | 0 | NEW | 2.5 | AllplanAttributes - ash_lichte Raumhöhe: 2.500000; OKFF: 0
Fliesen | WUN-H2-E00-094a | FLOORING | Fl1 0.2 m | 1116Bfl0000065268/01 | m² | Bodenbelagsarbeiten | 1 | 0.2 | 0 | 1 | Bodenfläche | Fl1 | 0 | 0 | NEW | AllplanAttributes - Bezeichnung: Fliesen; Raumnr. Bauherr: 2.11_A2_02; ash B_Aufbau: B2; ash B_Rutschhemmung: R10
Fliesen Mosaik | WUN-H2-E00-094a | FLOORING | Fl2 0.2 m | 1116Bfl0001169428/01 | m² | Bodenbelagsarbeiten | 1 | 0.2 | 0 | 1 | Bodenfläche | Fl2 | 0 | 0 | NEW | AllplanAttributes - Bezeichnung: Fliesen Mosaik; Raumnr. Bauherr: 2.11_A2_02; ash B_Aufbau: B3; ash B_Rutschhemmung: R10; ash B_Bewertungsgruppe Barfußbereich: B
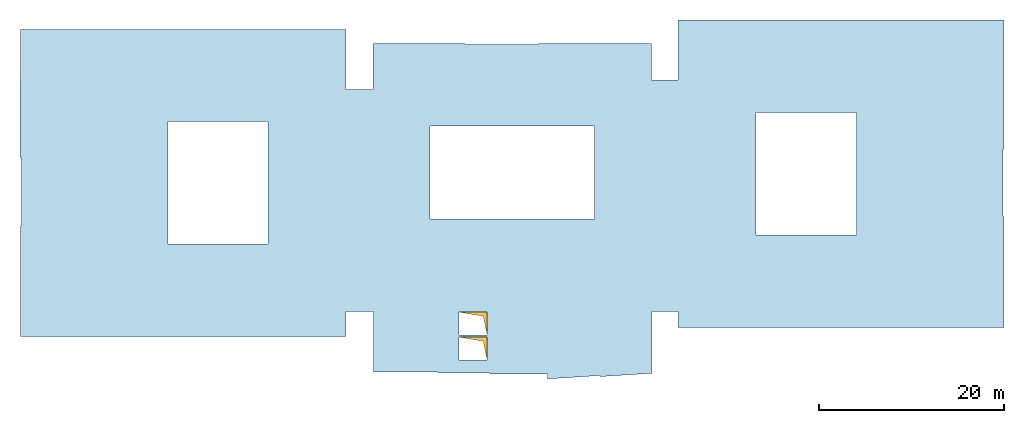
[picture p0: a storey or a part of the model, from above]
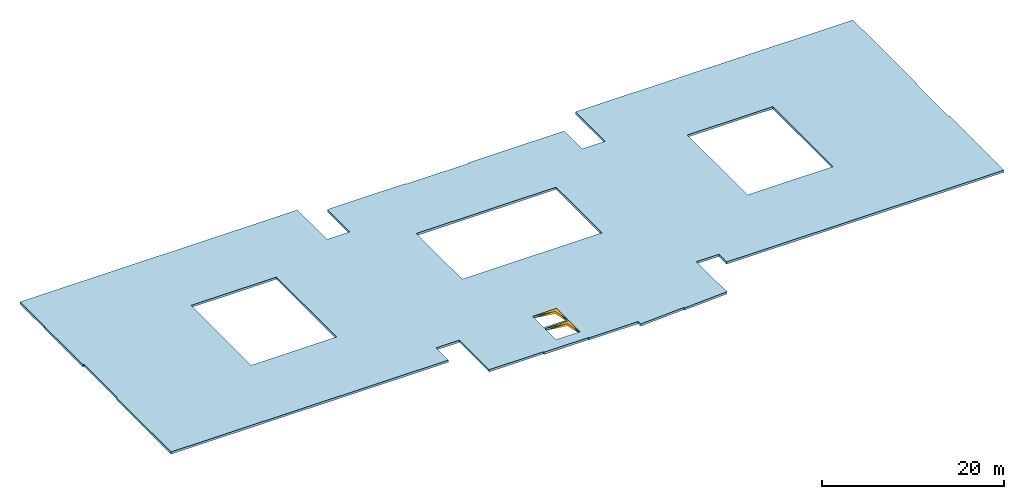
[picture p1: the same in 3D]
Properties of the parts of a building model (IFC4), part 19 of 80

# IfcCovering (3945)
Name | In | PredefinedType | Material | Allright_Bauteil_ID | Abrechnungsart | Gewerk | Schichtnummer | Schichtdicke (m) | Dicke (m) | Faktor | Objektname | AllplanAttributes, Material | Bezugshöhe | Deltahöhe | Status | D_lichte Raumhöhe [Zahl] (m)
Gipsfaserplatten 2-lagig (BSK) | WUN-H2-E00-094a | CEILING | layer 0.036 m | 1116Dfl0000065269/01 | m² | Trockenbauarbeiten | 1 | 0.036 | 0 | 1 | Deckenfläche |  | 0 | 0 | NEW | 2.5 | AllplanAttributes - Bezeichnung: Gipsfaserplatten 2-lagig (BSK)
Gipsfaserplatten 2-lagig (BSK) | WUN-H2-E00-094a | CEILING | Installationshöhe 0.764 m | 1116Dfl0000065269/02 | m² | Trockenbauarbeiten | 2 | 0.764 | 0 | 1 | Bekleidung | Installationshöhe | 0 | 0 | NEW | 2.5 | Pset_CoveringCommon - FireRating: für korrekte FläVisu; AllplanAttributes - ash_lichte Raumhöhe: 2.500000; OKFF: 0
Gipskarton, imprägniert | WUN-H2-E00-094a | CEILING | B 0.1 m | 1116Dfl0000065269/03 | m² | Trockenbauarbeiten | 3 | 0.1 | 0 | 1 | Bekleidung | B | 0 | 0 | NEW | 2.5 | AllplanAttributes - Bezeichnung: Gipskarton, imprägniert; ash_lichte Raumhöhe: 2.500000; OKFF: 0; Pset_CoveringCommon - FireRating: -; AcousticRating: -
Gipsfaserplatten 2-lagig (BSK) | WUN-H2-E00-094a | CEILING | D1 0.001 m | 1116Dfl0000065269/04 | m² | Maler- und Lackierarbeiten | 4 | 0.001 | 0 | 1 | Bekleidung | D1 | 0 | 0 | NEW | 2.5 | AllplanAttributes - ash_lichte Raumhöhe: 2.500000; OKFF: 0
Fliesen | WUN-H2-E00-091a | FLOORING | Fl1 0.2 m | 1116Bfl0000065266/01 | m² | Bodenbelagsarbeiten | 1 | 0.2 | 0 | 1 | Bodenfläche | Fl1 | 0 | 0 | NEW | AllplanAttributes - Bezeichnung: Fliesen; Raumnr. Bauherr: 2.11_A2_02; ash B_Aufbau: B2; ash B_Rutschhemmung: R10
Fliesen Mosaik | WUN-H2-E00-091a | FLOORING | Fl2 0.2 m | 1116Bfl0001168727/01 | m² | Bodenbelagsarbeiten | 1 | 0.2 | 0 | 1 | Bodenfläche | Fl2 | 0 | 0 | NEW | AllplanAttributes - Bezeichnung: Fliesen Mosaik; Raumnr. Bauherr: 2.11_A2_02; ash B_Aufbau: B3; ash B_Rutschhemmung: R10; ash B_Bewertungsgruppe Barfußbereich: B
Gipsfaserplatten 2-lagig (BSK) | WUN-H2-E00-091a | CEILING | layer 0.036 m | 1116Dfl0000065267/01 | m² | Trockenbauarbeiten | 1 | 0.036 | 0 | 1 | Deckenfläche |  | 0 | 0 | NEW | 2.5 | AllplanAttributes - Bezeichnung: Gipsfaserplatten 2-lagig (BSK)
Gipsfaserplatten 2-lagig (BSK) | WUN-H2-E00-091a | CEILING | Installationshöhe 0.764 m | 1116Dfl0000065267/02 | m² | Trockenbauarbeiten | 2 | 0.764 | 0 | 1 | Bekleidung | Installationshöhe | 0 | 0 | NEW | 2.5 | Pset_CoveringCommon - FireRating: für korrekte FläVisu; AllplanAttributes - ash_lichte Raumhöhe: 2.500000; OKFF: 0
Gipskarton, imprägniert | WUN-H2-E00-091a | CEILING | B 0.1 m | 1116Dfl0000065267/03 | m² | Trockenbauarbeiten | 3 | 0.1 | 0 | 1 | Bekleidung | B | 0 | 0 | NEW | 2.5 | AllplanAttributes - Bezeichnung: Gipskarton, imprägniert; ash_lichte Raumhöhe: 2.500000; OKFF: 0; Pset_CoveringCommon - FireRating: -; AcousticRating: -
Gipsfaserplatten 2-lagig (BSK) | WUN-H2-E00-091a | CEILING | D1 0.001 m | 1116Dfl0000065267/04 | m² | Maler- und Lackierarbeiten | 4 | 0.001 | 0 | 1 | Bekleidung | D1 | 0 | 0 | NEW | 2.5 | AllplanAttributes - ash_lichte Raumhöhe: 2.500000; OKFF: 0
Fliesen | WUN-H2-E00-095a | FLOORING | Fl1 0.2 m | 1116Bfl0000065262/01 | m² | Bodenbelagsarbeiten | 1 | 0.2 | 0 | 1 | Bodenfläche | Fl1 | 0 | 0 | NEW | AllplanAttributes - Bezeichnung: Fliesen; Raumnr. Bauherr: 2.11_A2_02; ash B_Aufbau: B2; ash B_Rutschhemmung: R10
Fliesen Mosaik | WUN-H2-E00-095a | FLOORING | Fl2 0.2 m | 1116Bfl0001185526/01 | m² | Bodenbelagsarbeiten | 1 | 0.2 | 0 | 1 | Bodenfläche | Fl2 | 0 | 0 | NEW | AllplanAttributes - Bezeichnung: Fliesen Mosaik; Raumnr. Bauherr: 2.11_A2_02; ash B_Aufbau: B3; ash B_Rutschhemmung: R10; ash B_Bewertungsgruppe Barfußbereich: B
Gipsfaserplatten 2-lagig (BSK) | WUN-H2-E00-095a | CEILING | layer 0.036 m | 1116Dfl0000065263/01 | m² | Trockenbauarbeiten | 1 | 0.036 | 0 | 1 | Deckenfläche |  | 0 | 0 | NEW | 2.5 | AllplanAttributes - Bezeichnung: Gipsfaserplatten 2-lagig (BSK)
Gipsfaserplatten 2-lagig (BSK) | WUN-H2-E00-095a | CEILING | Installationshöhe 0.764 m | 1116Dfl0000065263/02 | m² | Trockenbauarbeiten | 2 | 0.764 | 0 | 1 | Bekleidung | Installationshöhe | 0 | 0 | NEW | 2.5 | Pset_CoveringCommon - FireRating: für korrekte FläVisu; AllplanAttributes - ash_lichte Raumhöhe: 2.500000; OKFF: 0
Gipskarton, imprägniert | WUN-H2-E00-095a | CEILING | B 0.1 m | 1116Dfl0000065263/03 | m² | Trockenbauarbeiten | 3 | 0.1 | 0 | 1 | Bekleidung | B | 0 | 0 | NEW | 2.5 | AllplanAttributes - Bezeichnung: Gipskarton, imprägniert; ash_lichte Raumhöhe: 2.500000; OKFF: 0; Pset_CoveringCommon - FireRating: -; AcousticRating: -
Gipsfaserplatten 2-lagig (BSK) | WUN-H2-E00-095a | CEILING | D1 0.001 m | 1116Dfl0000065263/04 | m² | Maler- und Lackierarbeiten | 4 | 0.001 | 0 | 1 | Bekleidung | D1 | 0 | 0 | NEW | 2.5 | AllplanAttributes - ash_lichte Raumhöhe: 2.500000; OKFF: 0
Fliesen | WUN-H2-E00-024a | FLOORING | Fl1 0.2 m | 1116Bfl0000065242/01 | m² | Bodenbelagsarbeiten | 1 | 0.2 | 0 | 1 | Bodenfläche | Fl1 | 0 | 0 | NEW | AllplanAttributes - Bezeichnung: Fliesen; Raumnr. Bauherr: 2.11_A2_02; ash B_Aufbau: B2; ash B_Rutschhemmung: R10
Fliesen Mosaik | WUN-H2-E00-024a | FLOORING | Fl2 0.2 m | 1116Bfl0001164600/01 | m² | Bodenbelagsarbeiten | 1 | 0.2 | 0 | 1 | Bodenfläche | Fl2 | 0 | 0 | NEW | AllplanAttributes - Bezeichnung: Fliesen Mosaik; Raumnr. Bauherr: 2.11_A2_02; ash B_Aufbau: B3; ash B_Rutschhemmung: R10; ash B_Bewertungsgruppe Barfußbereich: B
Gipsfaserplatten 2-lagig (BSK) | WUN-H2-E00-024a | CEILING | layer 0.036 m | 1116Dfl0000065243/01 | m² | Trockenbauarbeiten | 1 | 0.036 | 0 | 1 | Deckenfläche |  | 0 | 0 | NEW | 2.5 | AllplanAttributes - Bezeichnung: Gipsfaserplatten 2-lagig (BSK)
Gipsfaserplatten 2-lagig (BSK) | WUN-H2-E00-024a | CEILING | Installationshöhe 0.764 m | 1116Dfl0000065243/02 | m² | Trockenbauarbeiten | 2 | 0.764 | 0 | 1 | Bekleidung | Installationshöhe | 0 | 0 | NEW | 2.5 | Pset_CoveringCommon - FireRating: für korrekte FläVisu; AllplanAttributes - ash_lichte Raumhöhe: 2.500000; OKFF: 0
Gipskarton, imprägniert | WUN-H2-E00-024a | CEILING | B 0.1 m | 1116Dfl0000065243/03 | m² | Trockenbauarbeiten | 3 | 0.1 | 0 | 1 | Bekleidung | B | 0 | 0 | NEW | 2.5 | AllplanAttributes - Bezeichnung: Gipskarton, imprägniert; ash_lichte Raumhöhe: 2.500000; OKFF: 0; Pset_CoveringCommon - FireRating: -; AcousticRating: -
Gipsfaserplatten 2-lagig (BSK) | WUN-H2-E00-024a | CEILING | D1 0.001 m | 1116Dfl0000065243/04 | m² | Maler- und Lackierarbeiten | 4 | 0.001 | 0 | 1 | Bekleidung | D1 | 0 | 0 | NEW | 2.5 | AllplanAttributes - ash_lichte Raumhöhe: 2.500000; OKFF: 0
Fliesen | WUN-H2-E00-025a | FLOORING | Fl1 0.2 m | 1116Bfl0000065240/01 | m² | Bodenbelagsarbeiten | 1 | 0.2 | 0 | 1 | Bodenfläche | Fl1 | 0 | 0 | NEW | AllplanAttributes - Bezeichnung: Fliesen; Raumnr. Bauherr: 2.11_A2_02; ash B_Aufbau: B2; ash B_Rutschhemmung: R10
Fliesen Mosaik | WUN-H2-E00-025a | FLOORING | Fl2 0.2 m | 1116Bfl0001164400/01 | m² | Bodenbelagsarbeiten | 1 | 0.2 | 0 | 1 | Bodenfläche | Fl2 | 0 | 0 | NEW | AllplanAttributes - Bezeichnung: Fliesen Mosaik; Raumnr. Bauherr: 2.11_A2_02; ash B_Aufbau: B3; ash B_Rutschhemmung: R10; ash B_Bewertungsgruppe Barfußbereich: B
Gipsfaserplatten 2-lagig (BSK) | WUN-H2-E00-025a | CEILING | layer 0.036 m | 1116Dfl0000065241/01 | m² | Trockenbauarbeiten | 1 | 0.036 | 0 | 1 | Deckenfläche |  | 0 | 0 | NEW | 2.5 | AllplanAttributes - Bezeichnung: Gipsfaserplatten 2-lagig (BSK)
Gipsfaserplatten 2-lagig (BSK) | WUN-H2-E00-025a | CEILING | Installationshöhe 0.764 m | 1116Dfl0000065241/02 | m² | Trockenbauarbeiten | 2 | 0.764 | 0 | 1 | Bekleidung | Installationshöhe | 0 | 0 | NEW | 2.5 | Pset_CoveringCommon - FireRating: für korrekte FläVisu; AllplanAttributes - ash_lichte Raumhöhe: 2.500000; OKFF: 0
Gipskarton, imprägniert | WUN-H2-E00-025a | CEILING | B 0.1 m | 1116Dfl0000065241/03 | m² | Trockenbauarbeiten | 3 | 0.1 | 0 | 1 | Bekleidung | B | 0 | 0 | NEW | 2.5 | AllplanAttributes - Bezeichnung: Gipskarton, imprägniert; ash_lichte Raumhöhe: 2.500000; OKFF: 0; Pset_CoveringCommon - FireRating: -; AcousticRating: -
Gipsfaserplatten 2-lagig (BSK) | WUN-H2-E00-025a | CEILING | D1 0.001 m | 1116Dfl0000065241/04 | m² | Maler- und Lackierarbeiten | 4 | 0.001 | 0 | 1 | Bekleidung | D1 | 0 | 0 | NEW | 2.5 | AllplanAttributes - ash_lichte Raumhöhe: 2.500000; OKFF: 0
 | WUN-H2-E00-046a | SKIRTINGBOARD |  | 1116Lei0000232049 | m |  |  |  |  | 1 | Leiste |  | 0 | 0 | NEW
Fliesen | WUN-H2-E00-046a | FLOORING | Fl1 0.2 m | 1116Bfl0000065228/01 | m² | Bodenbelagsarbeiten | 1 | 0.2 | 0 | 1 | Bodenfläche | Fl1 | 0 | 0 | NEW | AllplanAttributes - Bezeichnung: Fliesen; Raumnr. Bauherr: 2.11_A2_02; ash B_Aufbau: B2; ash B_Rutschhemmung: R10
Fliesen Mosaik | WUN-H2-E00-046a | FLOORING | Fl2 0.2 m | 1116Bfl0001166613/01 | m² | Bodenbelagsarbeiten | 1 | 0.2 | 0 | 1 | Bodenfläche | Fl2 | 0 | 0 | NEW | AllplanAttributes - Bezeichnung: Fliesen Mosaik; Raumnr. Bauherr: 2.11_A2_02; ash B_Aufbau: B3; ash B_Rutschhemmung: R10; ash B_Bewertungsgruppe Barfußbereich: B
Gipsfaserplatten 2-lagig (BSK) | WUN-H2-E00-046a | CEILING | layer 0.036 m | 1116Dfl0000065229/01 | m² | Trockenbauarbeiten | 1 | 0.036 | 0 | 1 | Deckenfläche |  | 0 | 0 | NEW | 2.5 | AllplanAttributes - Bezeichnung: Gipsfaserplatten 2-lagig (BSK)
Gipsfaserplatten 2-lagig (BSK) | WUN-H2-E00-046a | CEILING | Installationshöhe 0.764 m | 1116Dfl0000065229/02 | m² | Trockenbauarbeiten | 2 | 0.764 | 0 | 1 | Bekleidung | Installationshöhe | 0 | 0 | NEW | 2.5 | Pset_CoveringCommon - FireRating: für korrekte FläVisu; AllplanAttributes - ash_lichte Raumhöhe: 2.500000; OKFF: 0
Gipskarton, imprägniert | WUN-H2-E00-046a | CEILING | B 0.1 m | 1116Dfl0000065229/03 | m² | Trockenbauarbeiten | 3 | 0.1 | 0 | 1 | Bekleidung | B | 0 | 0 | NEW | 2.5 | AllplanAttributes - Bezeichnung: Gipskarton, imprägniert; ash_lichte Raumhöhe: 2.500000; OKFF: 0; Pset_CoveringCommon - FireRating: -; AcousticRating: -
Gipsfaserplatten 2-lagig (BSK) | WUN-H2-E00-046a | CEILING | D1 0.001 m | 1116Dfl0000065229/04 | m² | Maler- und Lackierarbeiten | 4 | 0.001 | 0 | 1 | Bekleidung | D1 | 0 | 0 | NEW | 2.5 | AllplanAttributes - ash_lichte Raumhöhe: 2.500000; OKFF: 0
Fliesen | WUN-H2-E00-023a | FLOORING | Fl1 0.2 m | 1116Bfl0000065232/01 | m² | Bodenbelagsarbeiten | 1 | 0.2 | 0 | 1 | Bodenfläche | Fl1 | 0 | 0 | NEW | AllplanAttributes - Bezeichnung: Fliesen; Raumnr. Bauherr: 2.11_A2_02; ash B_Aufbau: B2; ash B_Rutschhemmung: R10
Fliesen Mosaik | WUN-H2-E00-023a | FLOORING | Fl2 0.2 m | 1116Bfl0001164199/01 | m² | Bodenbelagsarbeiten | 1 | 0.2 | 0 | 1 | Bodenfläche | Fl2 | 0 | 0 | NEW | AllplanAttributes - Bezeichnung: Fliesen Mosaik; Raumnr. Bauherr: 2.11_A2_02; ash B_Aufbau: B3; ash B_Rutschhemmung: R10; ash B_Bewertungsgruppe Barfußbereich: B
Gipsfaserplatten 2-lagig (BSK) | WUN-H2-E00-023a | CEILING | layer 0.036 m | 1116Dfl0000065233/01 | m² | Trockenbauarbeiten | 1 | 0.036 | 0 | 1 | Deckenfläche |  | 0 | 0 | NEW | 2.5 | AllplanAttributes - Bezeichnung: Gipsfaserplatten 2-lagig (BSK)
Gipsfaserplatten 2-lagig (BSK) | WUN-H2-E00-023a | CEILING | Installationshöhe 0.764 m | 1116Dfl0000065233/02 | m² | Trockenbauarbeiten | 2 | 0.764 | 0 | 1 | Bekleidung | Installationshöhe | 0 | 0 | NEW | 2.5 | Pset_CoveringCommon - FireRating: für korrekte FläVisu; AllplanAttributes - ash_lichte Raumhöhe: 2.500000; OKFF: 0
Gipskarton, imprägniert | WUN-H2-E00-023a | CEILING | B 0.1 m | 1116Dfl0000065233/03 | m² | Trockenbauarbeiten | 3 | 0.1 | 0 | 1 | Bekleidung | B | 0 | 0 | NEW | 2.5 | AllplanAttributes - Bezeichnung: Gipskarton, imprägniert; ash_lichte Raumhöhe: 2.500000; OKFF: 0; Pset_CoveringCommon - FireRating: -; AcousticRating: -
Gipsfaserplatten 2-lagig (BSK) | WUN-H2-E00-023a | CEILING | D1 0.001 m | 1116Dfl0000065233/04 | m² | Maler- und Lackierarbeiten | 4 | 0.001 | 0 | 1 | Bekleidung | D1 | 0 | 0 | NEW | 2.5 | AllplanAttributes - ash_lichte Raumhöhe: 2.500000; OKFF: 0
Fliesen | WUN-H2-E00-022a | FLOORING | Fl1 0.2 m | 1116Bfl0000065234/01 | m² | Bodenbelagsarbeiten | 1 | 0.2 | 0 | 1 | Bodenfläche | Fl1 | 0 | 0 | NEW | AllplanAttributes - Bezeichnung: Fliesen; Raumnr. Bauherr: 2.11_A2_02; ash B_Aufbau: B2; ash B_Rutschhemmung: R10
Fliesen Mosaik | WUN-H2-E00-022a | FLOORING | Fl2 0.2 m | 1116Bfl0001163570/01 | m² | Bodenbelagsarbeiten | 1 | 0.2 | 0 | 1 | Bodenfläche | Fl2 | 0 | 0 | NEW | AllplanAttributes - Bezeichnung: Fliesen Mosaik; Raumnr. Bauherr: 2.11_A2_02; ash B_Aufbau: B3; ash B_Rutschhemmung: R10; ash B_Bewertungsgruppe Barfußbereich: B
Gipsfaserplatten 2-lagig (BSK) | WUN-H2-E00-022a | CEILING | layer 0.036 m | 1116Dfl0000065235/01 | m² | Trockenbauarbeiten | 1 | 0.036 | 0 | 1 | Deckenfläche |  | 0 | 0 | NEW | 2.5 | AllplanAttributes - Bezeichnung: Gipsfaserplatten 2-lagig (BSK)
Gipsfaserplatten 2-lagig (BSK) | WUN-H2-E00-022a | CEILING | Installationshöhe 0.764 m | 1116Dfl0000065235/02 | m² | Trockenbauarbeiten | 2 | 0.764 | 0 | 1 | Bekleidung | Installationshöhe | 0 | 0 | NEW | 2.5 | Pset_CoveringCommon - FireRating: für korrekte FläVisu; AllplanAttributes - ash_lichte Raumhöhe: 2.500000; OKFF: 0
Gipskarton, imprägniert | WUN-H2-E00-022a | CEILING | B 0.1 m | 1116Dfl0000065235/03 | m² | Trockenbauarbeiten | 3 | 0.1 | 0 | 1 | Bekleidung | B | 0 | 0 | NEW | 2.5 | AllplanAttributes - Bezeichnung: Gipskarton, imprägniert; ash_lichte Raumhöhe: 2.500000; OKFF: 0; Pset_CoveringCommon - FireRating: -; AcousticRating: -
Gipsfaserplatten 2-lagig (BSK) | WUN-H2-E00-022a | CEILING | D1 0.001 m | 1116Dfl0000065235/04 | m² | Maler- und Lackierarbeiten | 4 | 0.001 | 0 | 1 | Bekleidung | D1 | 0 | 0 | NEW | 2.5 | AllplanAttributes - ash_lichte Raumhöhe: 2.500000; OKFF: 0
Fliesen | WUN-H2-E00-021a | FLOORING | Fl1 0.2 m | 1116Bfl0000065236/01 | m² | Bodenbelagsarbeiten | 1 | 0.2 | 0 | 1 | Bodenfläche | Fl1 | 0 | 0 | NEW | AllplanAttributes - Bezeichnung: Fliesen; Raumnr. Bauherr: 2.11_A2_02; ash B_Aufbau: B2; ash B_Rutschhemmung: R10
Fliesen Mosaik | WUN-H2-E00-021a | FLOORING | Fl2 0.2 m | 1116Bfl0001164800/01 | m² | Bodenbelagsarbeiten | 1 | 0.2 | 0 | 1 | Bodenfläche | Fl2 | 0 | 0 | NEW | AllplanAttributes - Bezeichnung: Fliesen Mosaik; Raumnr. Bauherr: 2.11_A2_02; ash B_Aufbau: B3; ash B_Rutschhemmung: R10; ash B_Bewertungsgruppe Barfußbereich: B
Gipsfaserplatten 2-lagig (BSK) | WUN-H2-E00-021a | CEILING | layer 0.036 m | 1116Dfl0000065238/01 | m² | Trockenbauarbeiten | 1 | 0.036 | 0 | 1 | Deckenfläche |  | 0 | 0 | NEW | 2.5 | AllplanAttributes - Bezeichnung: Gipsfaserplatten 2-lagig (BSK)
Gipsfaserplatten 2-lagig (BSK) | WUN-H2-E00-021a | CEILING | Installationshöhe 0.764 m | 1116Dfl0000065238/02 | m² | Trockenbauarbeiten | 2 | 0.764 | 0 | 1 | Bekleidung | Installationshöhe | 0 | 0 | NEW | 2.5 | Pset_CoveringCommon - FireRating: für korrekte FläVisu; AllplanAttributes - ash_lichte Raumhöhe: 2.500000; OKFF: 0
Gipskarton, imprägniert | WUN-H2-E00-021a | CEILING | B 0.1 m | 1116Dfl0000065238/03 | m² | Trockenbauarbeiten | 3 | 0.1 | 0 | 1 | Bekleidung | B | 0 | 0 | NEW | 2.5 | AllplanAttributes - Bezeichnung: Gipskarton, imprägniert; ash_lichte Raumhöhe: 2.500000; OKFF: 0; Pset_CoveringCommon - FireRating: -; AcousticRating: -
Gipsfaserplatten 2-lagig (BSK) | WUN-H2-E00-021a | CEILING | D1 0.001 m | 1116Dfl0000065238/04 | m² | Maler- und Lackierarbeiten | 4 | 0.001 | 0 | 1 | Bekleidung | D1 | 0 | 0 | NEW | 2.5 | AllplanAttributes - ash_lichte Raumhöhe: 2.500000; OKFF: 0
Fliesen | WUN-H2-E00-020a | FLOORING | Fl1 0.2 m | 1116Bfl0000065237/01 | m² | Bodenbelagsarbeiten | 1 | 0.2 | 0 | 1 | Bodenfläche | Fl1 | 0 | 0 | NEW | AllplanAttributes - Bezeichnung: Fliesen; Raumnr. Bauherr: 2.11_A2_02; ash B_Aufbau: B2; ash B_Rutschhemmung: R10
Fliesen Mosaik | WUN-H2-E00-020a | FLOORING | Fl2 0.2 m | 1116Bfl0001165000/01 | m² | Bodenbelagsarbeiten | 1 | 0.2 | 0 | 1 | Bodenfläche | Fl2 | 0 | 0 | NEW | AllplanAttributes - Bezeichnung: Fliesen Mosaik; Raumnr. Bauherr: 2.11_A2_02; ash B_Aufbau: B3; ash B_Rutschhemmung: R10; ash B_Bewertungsgruppe Barfußbereich: B
Gipsfaserplatten 2-lagig (BSK) | WUN-H2-E00-020a | CEILING | layer 0.036 m | 1116Dfl0000065239/01 | m² | Trockenbauarbeiten | 1 | 0.036 | 0 | 1 | Deckenfläche |  | 0 | 0 | NEW | 2.5 | AllplanAttributes - Bezeichnung: Gipsfaserplatten 2-lagig (BSK)
Gipsfaserplatten 2-lagig (BSK) | WUN-H2-E00-020a | CEILING | Installationshöhe 0.764 m | 1116Dfl0000065239/02 | m² | Trockenbauarbeiten | 2 | 0.764 | 0 | 1 | Bekleidung | Installationshöhe | 0 | 0 | NEW | 2.5 | Pset_CoveringCommon - FireRating: für korrekte FläVisu; AllplanAttributes - ash_lichte Raumhöhe: 2.500000; OKFF: 0
Gipskarton, imprägniert | WUN-H2-E00-020a | CEILING | B 0.1 m | 1116Dfl0000065239/03 | m² | Trockenbauarbeiten | 3 | 0.1 | 0 | 1 | Bekleidung | B | 0 | 0 | NEW | 2.5 | AllplanAttributes - Bezeichnung: Gipskarton, imprägniert; ash_lichte Raumhöhe: 2.500000; OKFF: 0; Pset_CoveringCommon - FireRating: -; AcousticRating: -
Gipsfaserplatten 2-lagig (BSK) | WUN-H2-E00-020a | CEILING | D1 0.001 m | 1116Dfl0000065239/04 | m² | Maler- und Lackierarbeiten | 4 | 0.001 | 0 | 1 | Bekleidung | D1 | 0 | 0 | NEW | 2.5 | AllplanAttributes - ash_lichte Raumhöhe: 2.500000; OKFF: 0
 | WUN-H2-E00-042a | SKIRTINGBOARD |  | 1116Lei0000232016 | m |  |  |  |  | 1 | Leiste |  | 0 | 0 | NEW
Fliesen | WUN-H2-E00-042a | FLOORING | Fl1 0.2 m | 1116Bfl0000065224/01 | m² | Bodenbelagsarbeiten | 1 | 0.2 | 0 | 1 | Bodenfläche | Fl1 | 0 | 0 | NEW | AllplanAttributes - Bezeichnung: Fliesen; Raumnr. Bauherr: 2.11_A2_02; ash B_Aufbau: B2; ash B_Rutschhemmung: R10
Fliesen Mosaik | WUN-H2-E00-042a | FLOORING | Fl2 0.2 m | 1116Bfl0001165811/01 | m² | Bodenbelagsarbeiten | 1 | 0.2 | 0 | 1 | Bodenfläche | Fl2 | 0 | 0 | NEW | AllplanAttributes - Bezeichnung: Fliesen Mosaik; Raumnr. Bauherr: 2.11_A2_02; ash B_Aufbau: B3; ash B_Rutschhemmung: R10; ash B_Bewertungsgruppe Barfußbereich: B
Gipsfaserplatten 2-lagig (BSK) | WUN-H2-E00-042a | CEILING | layer 0.036 m | 1116Dfl0000065225/01 | m² | Trockenbauarbeiten | 1 | 0.036 | 0 | 1 | Deckenfläche |  | 0 | 0 | NEW | 2.5 | AllplanAttributes - Bezeichnung: Gipsfaserplatten 2-lagig (BSK)
Gipsfaserplatten 2-lagig (BSK) | WUN-H2-E00-042a | CEILING | Installationshöhe 0.764 m | 1116Dfl0000065225/02 | m² | Trockenbauarbeiten | 2 | 0.764 | 0 | 1 | Bekleidung | Installationshöhe | 0 | 0 | NEW | 2.5 | Pset_CoveringCommon - FireRating: für korrekte FläVisu; AllplanAttributes - ash_lichte Raumhöhe: 2.500000; OKFF: 0
Gipskarton, imprägniert | WUN-H2-E00-042a | CEILING | B 0.1 m | 1116Dfl0000065225/03 | m² | Trockenbauarbeiten | 3 | 0.1 | 0 | 1 | Bekleidung | B | 0 | 0 | NEW | 2.5 | AllplanAttributes - Bezeichnung: Gipskarton, imprägniert; ash_lichte Raumhöhe: 2.500000; OKFF: 0; Pset_CoveringCommon - FireRating: -; AcousticRating: -
Gipsfaserplatten 2-lagig (BSK) | WUN-H2-E00-042a | CEILING | D1 0.001 m | 1116Dfl0000065225/04 | m² | Maler- und Lackierarbeiten | 4 | 0.001 | 0 | 1 | Bekleidung | D1 | 0 | 0 | NEW | 2.5 | AllplanAttributes - ash_lichte Raumhöhe: 2.500000; OKFF: 0
Fliesen | WUN-H2-E00-064b | FLOORING | Fl1 0.2 m | 1116Bfl0000066430/01 | m² | Bodenbelagsarbeiten | 1 | 0.2 | 0 | 1 | Bodenfläche | Fl1 | 0 | 0 | AllplanAttributes - Bezeichnung: Fliesen; Raumnr. Bauherr: 2.11_A2_02; ash B_Aufbau: B2; ash B_Rutschhemmung: R10
Gipsfaserplatten 2-lagig (BSK) | WUN-H2-E00-064b | CEILING | layer 0.036 m | 1116Dfl0000066431/01 | m² | Trockenbauarbeiten | 1 | 0.036 | 0 | 1 | Deckenfläche |  | 0 | 0 |  | 2.5 | AllplanAttributes - Bezeichnung: Gipsfaserplatten 2-lagig (BSK)
 | WUN-H2-E00-064b | CEILING | Installationshöhe 0.764 m | 1116Dfl0000066431/02 | m² | Trockenbauarbeiten | 2 | 0.764 | 0 | 1 | Bekleidung | Installationshöhe | 0 | 0 |  | 2.5 | Pset_CoveringCommon - FireRating: für korrekte FläVisu; AllplanAttributes - ash_lichte Raumhöhe: 2.500000; OKFF: 0
Gipskarton, imprägniert | WUN-H2-E00-064b | CEILING | B 0.1 m | 1116Dfl0000066431/03 | m² | Trockenbauarbeiten | 3 | 0.1 | 0 | 1 | Bekleidung | B | 0 | 0 |  | 2.5 | AllplanAttributes - Bezeichnung: Gipskarton, imprägniert; ash_lichte Raumhöhe: 2.500000; OKFF: 0; Pset_CoveringCommon - FireRating: -; AcousticRating: -
 | WUN-H2-E00-064b | CEILING | D1 0.001 m | 1116Dfl0000066431/04 | m² | Maler- und Lackierarbeiten | 4 | 0.001 | 0 | 1 | Bekleidung | D1 | 0 | 0 | NEW | 2.5 | AllplanAttributes - ash_lichte Raumhöhe: 2.500000; OKFF: 0
Fliesen | WUN-H2-E00-012b | FLOORING | Fl1 0.2 m | 1116Bfl0000066422/01 | m² | Bodenbelagsarbeiten | 1 | 0.2 | 0 | 1 | Bodenfläche | Fl1 | 0 | 0 | AllplanAttributes - Bezeichnung: Fliesen; Raumnr. Bauherr: 2.11_A2_02; ash B_Aufbau: B2; ash B_Rutschhemmung: R10
Gipsfaserplatten 2-lagig (BSK) | WUN-H2-E00-012b | CEILING | layer 0.036 m | 1116Dfl0000066421/01 | m² | Trockenbauarbeiten | 1 | 0.036 | 0 | 1 | Deckenfläche |  | 0 | 0 |  | 2.5 | AllplanAttributes - Bezeichnung: Gipsfaserplatten 2-lagig (BSK)
 | WUN-H2-E00-012b | CEILING | Installationshöhe 0.764 m | 1116Dfl0000066421/02 | m² | Trockenbauarbeiten | 2 | 0.764 | 0 | 1 | Bekleidung | Installationshöhe | 0 | 0 |  | 2.5 | Pset_CoveringCommon - FireRating: für korrekte FläVisu; AllplanAttributes - ash_lichte Raumhöhe: 2.500000; OKFF: 0
Gipskarton, imprägniert | WUN-H2-E00-012b | CEILING | B 0.1 m | 1116Dfl0000066421/03 | m² | Trockenbauarbeiten | 3 | 0.1 | 0 | 1 | Bekleidung | B | 0 | 0 |  | 2.5 | AllplanAttributes - Bezeichnung: Gipskarton, imprägniert; ash_lichte Raumhöhe: 2.500000; OKFF: 0; Pset_CoveringCommon - FireRating: -; AcousticRating: -
 | WUN-H2-E00-012b | CEILING | D1 0.001 m | 1116Dfl0000066421/04 | m² | Maler- und Lackierarbeiten | 4 | 0.001 | 0 | 1 | Bekleidung | D1 | 0 | 0 | NEW | 2.5 | AllplanAttributes - ash_lichte Raumhöhe: 2.500000; OKFF: 0
Fliesen | WUN-H2-E00-052b | FLOORING | Fl1 0.2 m | 1116Bfl0000065673/01 | m² | Bodenbelagsarbeiten | 1 | 0.2 | 0 | 1 | Bodenfläche | Fl1 | 0 | 0 | AllplanAttributes - Bezeichnung: Fliesen; Raumnr. Bauherr: 2.11_A2_02; ash B_Aufbau: B2; ash B_Rutschhemmung: R10
Gipsfaserplatten 2-lagig (BSK) | WUN-H2-E00-052b | CEILING | layer 0.036 m | 1116Dfl0000065674/01 | m² | Trockenbauarbeiten | 1 | 0.036 | 0 | 1 | Deckenfläche |  | 0 | 0 |  | 2.5 | AllplanAttributes - Bezeichnung: Gipsfaserplatten 2-lagig (BSK)
 | WUN-H2-E00-052b | CEILING | Installationshöhe 0.764 m | 1116Dfl0000065674/02 | m² | Trockenbauarbeiten | 2 | 0.764 | 0 | 1 | Bekleidung | Installationshöhe | 0 | 0 |  | 2.5 | Pset_CoveringCommon - FireRating: für korrekte FläVisu; AllplanAttributes - ash_lichte Raumhöhe: 2.500000; OKFF: 0
Gipskarton, imprägniert | WUN-H2-E00-052b | CEILING | B 0.1 m | 1116Dfl0000065674/03 | m² | Trockenbauarbeiten | 3 | 0.1 | 0 | 1 | Bekleidung | B | 0 | 0 |  | 2.5 | AllplanAttributes - Bezeichnung: Gipskarton, imprägniert; ash_lichte Raumhöhe: 2.500000; OKFF: 0; Pset_CoveringCommon - FireRating: -; AcousticRating: -
 | WUN-H2-E00-052b | CEILING | D1 0.001 m | 1116Dfl0000065674/04 | m² | Maler- und Lackierarbeiten | 4 | 0.001 | 0 | 1 | Bekleidung | D1 | 0 | 0 | NEW | 2.5 | AllplanAttributes - ash_lichte Raumhöhe: 2.500000; OKFF: 0
Fliesen | WUN-H2-E00-074a | FLOORING | Fl1 0.2 m | 1116Bfl0000065246/01 | m² | Bodenbelagsarbeiten | 1 | 0.2 | 0 | 1 | Bodenfläche | Fl1 | 0 | 0 | NEW | AllplanAttributes - Bezeichnung: Fliesen; Raumnr. Bauherr: 2.11_A2_02; ash B_Aufbau: B2; ash B_Rutschhemmung: R10
Fliesen Mosaik | WUN-H2-E00-074a | FLOORING | Fl2 0.2 m | 1116Bfl0001168319/01 | m² | Bodenbelagsarbeiten | 1 | 0.2 | 0 | 1 | Bodenfläche | Fl2 | 0 | 0 | NEW | AllplanAttributes - Bezeichnung: Fliesen Mosaik; Raumnr. Bauherr: 2.11_A2_02; ash B_Aufbau: B3; ash B_Rutschhemmung: R10; ash B_Bewertungsgruppe Barfußbereich: B
Gipsfaserplatten 2-lagig (BSK) | WUN-H2-E00-074a | CEILING | layer 0.036 m | 1116Dfl0000065247/01 | m² | Trockenbauarbeiten | 1 | 0.036 | 0 | 1 | Deckenfläche |  | 0 | 0 | NEW | 2.5 | AllplanAttributes - Bezeichnung: Gipsfaserplatten 2-lagig (BSK)
Gipsfaserplatten 2-lagig (BSK) | WUN-H2-E00-074a | CEILING | Installationshöhe 0.764 m | 1116Dfl0000065247/02 | m² | Trockenbauarbeiten | 2 | 0.764 | 0 | 1 | Bekleidung | Installationshöhe | 0 | 0 | NEW | 2.5 | Pset_CoveringCommon - FireRating: für korrekte FläVisu; AllplanAttributes - ash_lichte Raumhöhe: 2.500000; OKFF: 0
Gipskarton, imprägniert | WUN-H2-E00-074a | CEILING | B 0.1 m | 1116Dfl0000065247/03 | m² | Trockenbauarbeiten | 3 | 0.1 | 0 | 1 | Bekleidung | B | 0 | 0 | NEW | 2.5 | AllplanAttributes - Bezeichnung: Gipskarton, imprägniert; ash_lichte Raumhöhe: 2.500000; OKFF: 0; Pset_CoveringCommon - FireRating: -; AcousticRating: -
Gipsfaserplatten 2-lagig (BSK) | WUN-H2-E00-074a | CEILING | D1 0.001 m | 1116Dfl0000065247/04 | m² | Maler- und Lackierarbeiten | 4 | 0.001 | 0 | 1 | Bekleidung | D1 | 0 | 0 | NEW | 2.5 | AllplanAttributes - ash_lichte Raumhöhe: 2.500000; OKFF: 0
Fliesen | WUN-H2-E00-072a | FLOORING | Fl1 0.2 m | 1116Bfl0000065252/01 | m² | Bodenbelagsarbeiten | 1 | 0.2 | 0 | 1 | Bodenfläche | Fl1 | 0 | 0 | NEW | AllplanAttributes - Bezeichnung: Fliesen; Raumnr. Bauherr: 2.11_A2_02; ash B_Aufbau: B2; ash B_Rutschhemmung: R10
Fliesen Mosaik | WUN-H2-E00-072a | FLOORING | Fl2 0.2 m | 1116Bfl0001167919/01 | m² | Bodenbelagsarbeiten | 1 | 0.2 | 0 | 1 | Bodenfläche | Fl2 | 0 | 0 | NEW | AllplanAttributes - Bezeichnung: Fliesen Mosaik; Raumnr. Bauherr: 2.11_A2_02; ash B_Aufbau: B3; ash B_Rutschhemmung: R10; ash B_Bewertungsgruppe Barfußbereich: B
Gipsfaserplatten 2-lagig (BSK) | WUN-H2-E00-072a | CEILING | layer 0.036 m | 1116Dfl0000065253/01 | m² | Trockenbauarbeiten | 1 | 0.036 | 0 | 1 | Deckenfläche |  | 0 | 0 | NEW | 2.5 | AllplanAttributes - Bezeichnung: Gipsfaserplatten 2-lagig (BSK)
Gipsfaserplatten 2-lagig (BSK) | WUN-H2-E00-072a | CEILING | Installationshöhe 0.764 m | 1116Dfl0000065253/02 | m² | Trockenbauarbeiten | 2 | 0.764 | 0 | 1 | Bekleidung | Installationshöhe | 0 | 0 | NEW | 2.5 | Pset_CoveringCommon - FireRating: für korrekte FläVisu; AllplanAttributes - ash_lichte Raumhöhe: 2.500000; OKFF: 0
Gipskarton, imprägniert | WUN-H2-E00-072a | CEILING | B 0.1 m | 1116Dfl0000065253/03 | m² | Trockenbauarbeiten | 3 | 0.1 | 0 | 1 | Bekleidung | B | 0 | 0 | NEW | 2.5 | AllplanAttributes - Bezeichnung: Gipskarton, imprägniert; ash_lichte Raumhöhe: 2.500000; OKFF: 0; Pset_CoveringCommon - FireRating: -; AcousticRating: -
Gipsfaserplatten 2-lagig (BSK) | WUN-H2-E00-072a | CEILING | D1 0.001 m | 1116Dfl0000065253/04 | m² | Maler- und Lackierarbeiten | 4 | 0.001 | 0 | 1 | Bekleidung | D1 | 0 | 0 | NEW | 2.5 | AllplanAttributes - ash_lichte Raumhöhe: 2.500000; OKFF: 0
Fliesen | WUN-H2-E00-071a | FLOORING | Fl1 0.2 m | 1116Bfl0000065254/01 | m² | Bodenbelagsarbeiten | 1 | 0.2 | 0 | 1 | Bodenfläche | Fl1 | 0 | 0 | NEW | AllplanAttributes - Bezeichnung: Fliesen; Raumnr. Bauherr: 2.11_A2_02; ash B_Aufbau: B2; ash B_Rutschhemmung: R10
Fliesen Mosaik | WUN-H2-E00-071a | FLOORING | Fl2 0.2 m | 1116Bfl0001167719/01 | m² | Bodenbelagsarbeiten | 1 | 0.2 | 0 | 1 | Bodenfläche | Fl2 | 0 | 0 | NEW | AllplanAttributes - Bezeichnung: Fliesen Mosaik; Raumnr. Bauherr: 2.11_A2_02; ash B_Aufbau: B3; ash B_Rutschhemmung: R10; ash B_Bewertungsgruppe Barfußbereich: B
Gipsfaserplatten 2-lagig (BSK) | WUN-H2-E00-071a | CEILING | layer 0.036 m | 1116Dfl0000065255/01 | m² | Trockenbauarbeiten | 1 | 0.036 | 0 | 1 | Deckenfläche |  | 0 | 0 | NEW | 2.5 | AllplanAttributes - Bezeichnung: Gipsfaserplatten 2-lagig (BSK)
Gipsfaserplatten 2-lagig (BSK) | WUN-H2-E00-071a | CEILING | Installationshöhe 0.764 m | 1116Dfl0000065255/02 | m² | Trockenbauarbeiten | 2 | 0.764 | 0 | 1 | Bekleidung | Installationshöhe | 0 | 0 | NEW | 2.5 | Pset_CoveringCommon - FireRating: für korrekte FläVisu; AllplanAttributes - ash_lichte Raumhöhe: 2.500000; OKFF: 0
Gipskarton, imprägniert | WUN-H2-E00-071a | CEILING | B 0.1 m | 1116Dfl0000065255/03 | m² | Trockenbauarbeiten | 3 | 0.1 | 0 | 1 | Bekleidung | B | 0 | 0 | NEW | 2.5 | AllplanAttributes - Bezeichnung: Gipskarton, imprägniert; ash_lichte Raumhöhe: 2.500000; OKFF: 0; Pset_CoveringCommon - FireRating: -; AcousticRating: -
Gipsfaserplatten 2-lagig (BSK) | WUN-H2-E00-071a | CEILING | D1 0.001 m | 1116Dfl0000065255/04 | m² | Maler- und Lackierarbeiten | 4 | 0.001 | 0 | 1 | Bekleidung | D1 | 0 | 0 | NEW | 2.5 | AllplanAttributes - ash_lichte Raumhöhe: 2.500000; OKFF: 0
Fliesen | WUN-H2-E00-070a | FLOORING | Fl1 0.2 m | 1116Bfl0000065249/01 | m² | Bodenbelagsarbeiten | 1 | 0.2 | 0 | 1 | Bodenfläche | Fl1 | 0 | 0 | NEW | AllplanAttributes - Bezeichnung: Fliesen; Raumnr. Bauherr: 2.11_A2_02; ash B_Aufbau: B2; ash B_Rutschhemmung: R10
Fliesen Mosaik | WUN-H2-E00-070a | FLOORING | Fl2 0.2 m | 1116Bfl0001167519/01 | m² | Bodenbelagsarbeiten | 1 | 0.2 | 0 | 1 | Bodenfläche | Fl2 | 0 | 0 | NEW | AllplanAttributes - Bezeichnung: Fliesen Mosaik; Raumnr. Bauherr: 2.11_A2_02; ash B_Aufbau: B3; ash B_Rutschhemmung: R10; ash B_Bewertungsgruppe Barfußbereich: B
Gipsfaserplatten 2-lagig (BSK) | WUN-H2-E00-070a | CEILING | layer 0.036 m | 1116Dfl0000065251/01 | m² | Trockenbauarbeiten | 1 | 0.036 | 0 | 1 | Deckenfläche |  | 0 | 0 | NEW | 2.5 | AllplanAttributes - Bezeichnung: Gipsfaserplatten 2-lagig (BSK)
Gipsfaserplatten 2-lagig (BSK) | WUN-H2-E00-070a | CEILING | Installationshöhe 0.764 m | 1116Dfl0000065251/02 | m² | Trockenbauarbeiten | 2 | 0.764 | 0 | 1 | Bekleidung | Installationshöhe | 0 | 0 | NEW | 2.5 | Pset_CoveringCommon - FireRating: für korrekte FläVisu; AllplanAttributes - ash_lichte Raumhöhe: 2.500000; OKFF: 0
Gipskarton, imprägniert | WUN-H2-E00-070a | CEILING | B 0.1 m | 1116Dfl0000065251/03 | m² | Trockenbauarbeiten | 3 | 0.1 | 0 | 1 | Bekleidung | B | 0 | 0 | NEW | 2.5 | AllplanAttributes - Bezeichnung: Gipskarton, imprägniert; ash_lichte Raumhöhe: 2.500000; OKFF: 0; Pset_CoveringCommon - FireRating: -; AcousticRating: -
Gipsfaserplatten 2-lagig (BSK) | WUN-H2-E00-070a | CEILING | D1 0.001 m | 1116Dfl0000065251/04 | m² | Maler- und Lackierarbeiten | 4 | 0.001 | 0 | 1 | Bekleidung | D1 | 0 | 0 | NEW | 2.5 | AllplanAttributes - ash_lichte Raumhöhe: 2.500000; OKFF: 0
Fliesen | WUN-H2-E00-069a | FLOORING | Fl1 0.2 m | 1116Bfl0000065248/01 | m² | Bodenbelagsarbeiten | 1 | 0.2 | 0 | 1 | Bodenfläche | Fl1 | 0 | 0 | NEW | AllplanAttributes - Bezeichnung: Fliesen; Raumnr. Bauherr: 2.11_A2_02; ash B_Aufbau: B2; ash B_Rutschhemmung: R10
Fliesen Mosaik | WUN-H2-E00-069a | FLOORING | Fl2 0.2 m | 1116Bfl0001167319/01 | m² | Bodenbelagsarbeiten | 1 | 0.2 | 0 | 1 | Bodenfläche | Fl2 | 0 | 0 | NEW | AllplanAttributes - Bezeichnung: Fliesen Mosaik; Raumnr. Bauherr: 2.11_A2_02; ash B_Aufbau: B3; ash B_Rutschhemmung: R10; ash B_Bewertungsgruppe Barfußbereich: B
Gipsfaserplatten 2-lagig (BSK) | WUN-H2-E00-069a | CEILING | layer 0.036 m | 1116Dfl0000065250/01 | m² | Trockenbauarbeiten | 1 | 0.036 | 0 | 1 | Deckenfläche |  | 0 | 0 | NEW | 2.5 | AllplanAttributes - Bezeichnung: Gipsfaserplatten 2-lagig (BSK)
Gipsfaserplatten 2-lagig (BSK) | WUN-H2-E00-069a | CEILING | Installationshöhe 0.764 m | 1116Dfl0000065250/02 | m² | Trockenbauarbeiten | 2 | 0.764 | 0 | 1 | Bekleidung | Installationshöhe | 0 | 0 | NEW | 2.5 | Pset_CoveringCommon - FireRating: für korrekte FläVisu; AllplanAttributes - ash_lichte Raumhöhe: 2.500000; OKFF: 0
Gipskarton, imprägniert | WUN-H2-E00-069a | CEILING | B 0.1 m | 1116Dfl0000065250/03 | m² | Trockenbauarbeiten | 3 | 0.1 | 0 | 1 | Bekleidung | B | 0 | 0 | NEW | 2.5 | AllplanAttributes - Bezeichnung: Gipskarton, imprägniert; ash_lichte Raumhöhe: 2.500000; OKFF: 0; Pset_CoveringCommon - FireRating: -; AcousticRating: -
Gipsfaserplatten 2-lagig (BSK) | WUN-H2-E00-069a | CEILING | D1 0.001 m | 1116Dfl0000065250/04 | m² | Maler- und Lackierarbeiten | 4 | 0.001 | 0 | 1 | Bekleidung | D1 | 0 | 0 | NEW | 2.5 | AllplanAttributes - ash_lichte Raumhöhe: 2.500000; OKFF: 0
Fliesen | WUN-H2-E00-068a | FLOORING | Fl1 0.2 m | 1116Bfl0000066846/01 | m² | Bodenbelagsarbeiten | 1 | 0.2 | 0 | 1 | Bodenfläche | Fl1 | 0 | 0 | NEW | AllplanAttributes - Bezeichnung: Fliesen; Raumnr. Bauherr: 2.11_A2_02; ash B_Aufbau: B2; ash B_Rutschhemmung: R10
Fliesen Mosaik | WUN-H2-E00-068a | FLOORING | Fl2 0.2 m | 1116Bfl0001167118/01 | m² | Bodenbelagsarbeiten | 1 | 0.2 | 0 | 1 | Bodenfläche | Fl2 | 0 | 0 | NEW | AllplanAttributes - Bezeichnung: Fliesen Mosaik; Raumnr. Bauherr: 2.11_A2_02; ash B_Aufbau: B3; ash B_Rutschhemmung: R10; ash B_Bewertungsgruppe Barfußbereich: B
Gipsfaserplatten 2-lagig (BSK) | WUN-H2-E00-068a | CEILING | layer 0.036 m | 1116Dfl0000066847/01 | m² | Trockenbauarbeiten | 1 | 0.036 | 0 | 1 | Deckenfläche |  | 0 | 0 | NEW | 2.5 | AllplanAttributes - Bezeichnung: Gipsfaserplatten 2-lagig (BSK)
Gipsfaserplatten 2-lagig (BSK) | WUN-H2-E00-068a | CEILING | Installationshöhe 0.764 m | 1116Dfl0000066847/02 | m² | Trockenbauarbeiten | 2 | 0.764 | 0 | 1 | Bekleidung | Installationshöhe | 0 | 0 | NEW | 2.5 | Pset_CoveringCommon - FireRating: für korrekte FläVisu; AllplanAttributes - ash_lichte Raumhöhe: 2.500000; OKFF: 0
Gipskarton, imprägniert | WUN-H2-E00-068a | CEILING | B 0.1 m | 1116Dfl0000066847/03 | m² | Trockenbauarbeiten | 3 | 0.1 | 0 | 1 | Bekleidung | B | 0 | 0 | NEW | 2.5 | AllplanAttributes - Bezeichnung: Gipskarton, imprägniert; ash_lichte Raumhöhe: 2.500000; OKFF: 0; Pset_CoveringCommon - FireRating: -; AcousticRating: -
Gipsfaserplatten 2-lagig (BSK) | WUN-H2-E00-068a | CEILING | D1 0.001 m | 1116Dfl0000066847/04 | m² | Maler- und Lackierarbeiten | 4 | 0.001 | 0 | 1 | Bekleidung | D1 | 0 | 0 | NEW | 2.5 | AllplanAttributes - ash_lichte Raumhöhe: 2.500000; OKFF: 0
Fliesen | WUN-H2-E00-073a | FLOORING | Fl1 0.2 m | 1116Bfl0000065256/01 | m² | Bodenbelagsarbeiten | 1 | 0.2 | 0 | 1 | Bodenfläche | Fl1 | 0 | 0 | NEW | AllplanAttributes - Bezeichnung: Fliesen; Raumnr. Bauherr: 2.11_A2_02; ash B_Aufbau: B2; ash B_Rutschhemmung: R10
Fliesen Mosaik | WUN-H2-E00-073a | FLOORING | Fl2 0.2 m | 1116Bfl0001168119/01 | m² | Bodenbelagsarbeiten | 1 | 0.2 | 0 | 1 | Bodenfläche | Fl2 | 0 | 0 | NEW | AllplanAttributes - Bezeichnung: Fliesen Mosaik; Raumnr. Bauherr: 2.11_A2_02; ash B_Aufbau: B3; ash B_Rutschhemmung: R10; ash B_Bewertungsgruppe Barfußbereich: B
Gipsfaserplatten 2-lagig (BSK) | WUN-H2-E00-073a | CEILING | layer 0.036 m | 1116Dfl0000065257/01 | m² | Trockenbauarbeiten | 1 | 0.036 | 0 | 1 | Deckenfläche |  | 0 | 0 | NEW | 2.5 | AllplanAttributes - Bezeichnung: Gipsfaserplatten 2-lagig (BSK)
Gipsfaserplatten 2-lagig (BSK) | WUN-H2-E00-073a | CEILING | Installationshöhe 0.764 m | 1116Dfl0000065257/02 | m² | Trockenbauarbeiten | 2 | 0.764 | 0 | 1 | Bekleidung | Installationshöhe | 0 | 0 | NEW | 2.5 | Pset_CoveringCommon - FireRating: für korrekte FläVisu; AllplanAttributes - ash_lichte Raumhöhe: 2.500000; OKFF: 0
Gipskarton, imprägniert | WUN-H2-E00-073a | CEILING | B 0.1 m | 1116Dfl0000065257/03 | m² | Trockenbauarbeiten | 3 | 0.1 | 0 | 1 | Bekleidung | B | 0 | 0 | NEW | 2.5 | AllplanAttributes - Bezeichnung: Gipskarton, imprägniert; ash_lichte Raumhöhe: 2.500000; OKFF: 0; Pset_CoveringCommon - FireRating: -; AcousticRating: -
Gipsfaserplatten 2-lagig (BSK) | WUN-H2-E00-073a | CEILING | D1 0.001 m | 1116Dfl0000065257/04 | m² | Maler- und Lackierarbeiten | 4 | 0.001 | 0 | 1 | Bekleidung | D1 | 0 | 0 | NEW | 2.5 | AllplanAttributes - ash_lichte Raumhöhe: 2.500000; OKFF: 0
Gipsfaserplatten 2-lagig (BSK) | WUN-H2-E00-029 | CEILING | layer 0.036 m | 1116Dfl0000065339/01 | m² | Trockenbauarbeiten | 1 | 0.036 | 0 | 1 | Deckenfläche |  | 0 | 0 | NEW | 2.5 | AllplanAttributes - Bezeichnung: Gipsfaserplatten 2-lagig (BSK)
Gipsfaserplatten 2-lagig (BSK) | WUN-H2-E00-029 | CEILING | Installationshöhe 0.764 m | 1116Dfl0000065339/02 | m² | Trockenbauarbeiten | 2 | 0.764 | 0 | 1 | Bekleidung | Installationshöhe | 0 | 0 | NEW | 2.5 | Pset_CoveringCommon - FireRating: für korrekte FläVisu; AllplanAttributes - ash_lichte Raumhöhe: (3400-36+764+100)/1000-0
Rasterdecke | WUN-H2-E00-029 | CEILING | E3 0.1 m | 1116Dfl0000065339/03 | m² | Trockenbauarbeiten | 3 | 0.1 | 0 | 1 | Bekleidung | E3 | 0 | 0 | NEW | 2.5 | AllplanAttributes - Bezeichnung: Rasterdecke; ash_lichte Raumhöhe: (3400-36+764+100)/1000-0; Pset_CoveringCommon - FireRating: -; AcousticRating: -
PVC Bahnenware Uni | WUN-H2-E00-029 | FLOORING | Ku2 0.2 m | 1116Bfl0000065338/01 | m² | Bodenbelagsarbeiten | 1 | 0.2 | 0 | 1 | Bodenfläche | Ku2 | 0 | 0 | NEW | AllplanAttributes - Bezeichnung: PVC Bahnenware Uni; Raumnr. Bauherr: 2.11_A2_02; ash B_Aufbau: B1; ash B_Rutschhemmung: R9
Gipsfaserplatten 2-lagig (BSK) | WUN-H2-E00-081 | CEILING | layer 0.036 m | 1116Dfl0000065336/01 | m² | Trockenbauarbeiten | 1 | 0.036 | 0 | 1 | Deckenfläche |  | 0 | 0 | NEW | 2.5 | AllplanAttributes - Bezeichnung: Gipsfaserplatten 2-lagig (BSK)
Gipsfaserplatten 2-lagig (BSK) | WUN-H2-E00-081 | CEILING | Installationshöhe 0.764 m | 1116Dfl0000065336/02 | m² | Trockenbauarbeiten | 2 | 0.764 | 0 | 1 | Bekleidung | Installationshöhe | 0 | 0 | NEW | 2.5 | Pset_CoveringCommon - FireRating: für korrekte FläVisu; AllplanAttributes - ash_lichte Raumhöhe: (3400-36+764+100)/1000-0
Rasterdecke | WUN-H2-E00-081 | CEILING | E3 0.1 m | 1116Dfl0000065336/03 | m² | Trockenbauarbeiten | 3 | 0.1 | 0 | 1 | Bekleidung | E3 | 0 | 0 | NEW | 2.5 | AllplanAttributes - Bezeichnung: Rasterdecke; ash_lichte Raumhöhe: (3400-36+764+100)/1000-0; Pset_CoveringCommon - FireRating: -; AcousticRating: -
PVC Bahnenware Uni | WUN-H2-E00-081 | FLOORING | Ku2 0.2 m | 1116Bfl0000065337/01 | m² | Bodenbelagsarbeiten | 1 | 0.2 | 0 | 1 | Bodenfläche | Ku2 | 0 | 0 | NEW | AllplanAttributes - Bezeichnung: PVC Bahnenware Uni; Raumnr. Bauherr: 2.11_A2_02; ash B_Aufbau: B1; ash B_Rutschhemmung: R9
Fliesen | WUN-H2-E00-062 | FLOORING | Fl1 0.2 m | 1116Bfl0000066858/01 | m² | Bodenbelagsarbeiten | 1 | 0.2 | 0 | 1 | Bodenfläche | Fl1 | 0 | 0 | AllplanAttributes - Bezeichnung: Fliesen; Raumnr. Bauherr: 2.11_A2_02; ash B_Aufbau: B2; ash B_Rutschhemmung: R10
Gipsfaserplatten 2-lagig (BSK) | WUN-H2-E00-062 | CEILING | layer 0.036 m | 1116Dfl0000066859/01 | m² | Trockenbauarbeiten | 1 | 0.036 | 0 | 1 | Deckenfläche |  | 0 | 0 |  | 2.5 | AllplanAttributes - Bezeichnung: Gipsfaserplatten 2-lagig (BSK)
 | WUN-H2-E00-062 | CEILING | Installationshöhe 0.764 m | 1116Dfl0000066859/02 | m² | Trockenbauarbeiten | 2 | 0.764 | 0 | 1 | Bekleidung | Installationshöhe | 0 | 0 |  | 2.5 | Pset_CoveringCommon - FireRating: für korrekte FläVisu; AllplanAttributes - ash_lichte Raumhöhe: 2.500000; OKFF: 0
Gipskarton, imprägniert | WUN-H2-E00-062 | CEILING | B 0.1 m | 1116Dfl0000066859/03 | m² | Trockenbauarbeiten | 3 | 0.1 | 0 | 1 | Bekleidung | B | 0 | 0 |  | 2.5 | AllplanAttributes - Bezeichnung: Gipskarton, imprägniert; ash_lichte Raumhöhe: 2.500000; OKFF: 0; Pset_CoveringCommon - FireRating: -; AcousticRating: -
 | WUN-H2-E00-062 | CEILING | D1 0.001 m | 1116Dfl0000066859/04 | m² | Maler- und Lackierarbeiten | 4 | 0.001 | 0 | 1 | Bekleidung | D1 | 0 | 0 | NEW | 2.5 | AllplanAttributes - ash_lichte Raumhöhe: 2.500000; OKFF: 0
Fliesen | WUN-H2-E00-041a | FLOORING | Fl1 0.2 m | 1116Bfl0000065226/01 | m² | Bodenbelagsarbeiten | 1 | 0.2 | 0 | 1 | Bodenfläche | Fl1 | 0 | 0 | NEW | AllplanAttributes - Bezeichnung: Fliesen; Raumnr. Bauherr: 2.11_A2_02; ash B_Aufbau: B2; ash B_Rutschhemmung: R10
Fliesen Mosaik | WUN-H2-E00-041a | FLOORING | Fl2 0.2 m | 1116Bfl0001165610/01 | m² | Bodenbelagsarbeiten | 1 | 0.2 | 0 | 1 | Bodenfläche | Fl2 | 0 | 0 | NEW | AllplanAttributes - Bezeichnung: Fliesen Mosaik; Raumnr. Bauherr: 2.11_A2_02; ash B_Aufbau: B3; ash B_Rutschhemmung: R10; ash B_Bewertungsgruppe Barfußbereich: B
Gipsfaserplatten 2-lagig (BSK) | WUN-H2-E00-041a | CEILING | layer 0.036 m | 1116Dfl0000065227/01 | m² | Trockenbauarbeiten | 1 | 0.036 | 0 | 1 | Deckenfläche |  | 0 | 0 | NEW | 2.5 | AllplanAttributes - Bezeichnung: Gipsfaserplatten 2-lagig (BSK)
Gipsfaserplatten 2-lagig (BSK) | WUN-H2-E00-041a | CEILING | Installationshöhe 0.764 m | 1116Dfl0000065227/02 | m² | Trockenbauarbeiten | 2 | 0.764 | 0 | 1 | Bekleidung | Installationshöhe | 0 | 0 | NEW | 2.5 | Pset_CoveringCommon - FireRating: für korrekte FläVisu; AllplanAttributes - ash_lichte Raumhöhe: 2.500000; OKFF: 0
Gipskarton, imprägniert | WUN-H2-E00-041a | CEILING | B 0.1 m | 1116Dfl0000065227/03 | m² | Trockenbauarbeiten | 3 | 0.1 | 0 | 1 | Bekleidung | B | 0 | 0 | NEW | 2.5 | AllplanAttributes - Bezeichnung: Gipskarton, imprägniert; ash_lichte Raumhöhe: 2.500000; OKFF: 0; Pset_CoveringCommon - FireRating: -; AcousticRating: -
Gipsfaserplatten 2-lagig (BSK) | WUN-H2-E00-041a | CEILING | D1 0.001 m | 1116Dfl0000065227/04 | m² | Maler- und Lackierarbeiten | 4 | 0.001 | 0 | 1 | Bekleidung | D1 | 0 | 0 | NEW | 2.5 | AllplanAttributes - ash_lichte Raumhöhe: 2.500000; OKFF: 0
Gipsfaserplatten 2-lagig (BSK) | WUN-H2-E00-002 | CEILING | layer 0.036 m | 1116Dfl0000065554/01 | m² | Trockenbauarbeiten | 1 | 0.036 | 0 | 1 | Deckenfläche |  | 0 | 0 | NEW | 2.5 | AllplanAttributes - Bezeichnung: Gipsfaserplatten 2-lagig (BSK)
Gipsfaserplatten 2-lagig (BSK) | WUN-H2-E00-002 | CEILING | Installationshöhe 0.764 m | 1116Dfl0000065554/02 | m² | Trockenbauarbeiten | 2 | 0.764 | 0 | 1 | Bekleidung | Installationshöhe | 0 | 0 | NEW | 2.5 | Pset_CoveringCommon - FireRating: für korrekte FläVisu; AllplanAttributes - ash_lichte Raumhöhe: (3400-36+764+100)/1000-0
Rasterdecke | WUN-H2-E00-002 | CEILING | E3 0.1 m | 1116Dfl0000065554/03 | m² | Trockenbauarbeiten | 3 | 0.1 | 0 | 1 | Bekleidung | E3 | 0 | 0 | NEW | 2.5 | AllplanAttributes - Bezeichnung: Rasterdecke; ash_lichte Raumhöhe: (3400-36+764+100)/1000-0; Pset_CoveringCommon - FireRating: -; AcousticRating: -
PVC Bahnenware Uni | WUN-H2-E00-002 | FLOORING | Ku2 0.2 m | 1116Bfl0000065553/01 | m² | Bodenbelagsarbeiten | 1 | 0.2 | 0 | 1 | Bodenfläche | Ku2 | 0 | 0 | NEW | AllplanAttributes - Bezeichnung: PVC Bahnenware Uni; Raumnr. Bauherr: 2.11_A2_02; ash B_Aufbau: B1; ash B_Rutschhemmung: R9
PVC Bahnenware Holzoptik | WUN-H2-E00-F03b | FLOORING | Ku1 0.2 m | 1116Bfl0000066615/01 | m² | Bodenbelagsarbeiten | 1 | 0.2 | 0 | 1 | Bodenfläche | Ku1 | 0 | 0 | NEW | AllplanAttributes - Bezeichnung: PVC Bahnenware Holzoptik; Raumnr. Bauherr: 2.11_A2_02; ash B_Aufbau: B1; ash B_Rutschhemmung: R9
Gipsfaserplatten 2-lagig (BSK) | WUN-H2-E00-F03b | CEILING | layer 0.036 m | 1116Dfl0000436750/01 | m² | Trockenbauarbeiten | 1 | 0.036 | 0 | 1 | Deckenfläche |  | 0 | 0 | NEW | 2.5 | AllplanAttributes - Bezeichnung: Gipsfaserplatten 2-lagig (BSK)
Gipsfaserplatten 2-lagig (BSK) | WUN-H2-E00-F03b | CEILING | Installationshöhe 0.714 m | 1116Dfl0000436750/02 | m² | Trockenbauarbeiten | 2 | 0.714 | 0 | 1 | Bekleidung | Installationshöhe | 0 | 0 | NEW | 2.5 | Pset_CoveringCommon - FireRating: für korrekte FläVisu; AllplanAttributes - ash_lichte Raumhöhe: 2.500000; OKFF: 0
Gipsfaserplatten 2-lagig (BSK) | WUN-H2-E00-F03b | CEILING | Aa 0.15 m | 1116Dfl0000436750/03 | m² | Trockenbauarbeiten | 3 | 0.15 | 0 | 1 | Bekleidung | Aa | 0 | 0 | NEW | 2.5 | Pset_CoveringCommon - FireRating: -; AcousticRating: -; AllplanAttributes - ash_lichte Raumhöhe: 2.500000; OKFF: 0
Gipsfaserplatten 2-lagig (BSK) | WUN-H2-E00-F03b | CEILING | D1 0.001 m | 1116Dfl0000436750/04 | m² | Maler- und Lackierarbeiten | 4 | 0.001 | 0 | 1 | Bekleidung | D1 | 0 | 0 | NEW | 2.5 | AllplanAttributes - ash_lichte Raumhöhe: 2.500000; OKFF: 0
Gipsfaserplatten 2-lagig (BSK) | WUN-H2-E00-F03b | CEILING | layer 0.036 m | 1116Dfl0000066614/01 | m² | Trockenbauarbeiten | 1 | 0.036 | 0 | 1 | Deckenfläche |  | 0 | 0 | NEW | 2.5 | AllplanAttributes - Bezeichnung: Gipsfaserplatten 2-lagig (BSK)
Gipsfaserplatten 2-lagig (BSK) | WUN-H2-E00-F03b | CEILING | Installationshöhe 0.714 m | 1116Dfl0000066614/02 | m² | Trockenbauarbeiten | 2 | 0.714 | 0 | 1 | Bekleidung | Installationshöhe | 0 | 0 | NEW | 2.5 | Pset_CoveringCommon - FireRating: für korrekte FläVisu; AllplanAttributes - ash_lichte Raumhöhe: 2.500000
Gipsfaserplatten 2-lagig (BSK) | WUN-H2-E00-F03b | CEILING | A1 0.15 m | 1116Dfl0000066614/03 | m² | Trockenbauarbeiten | 3 | 0.15 | 0 | 1 | Bekleidung | A1 | 0 | 0 | NEW | 2.5 | AllplanAttributes - ash_lichte Raumhöhe: 2.500000; Pset_CoveringCommon - AcousticRating: -
Gipsfaserplatten 2-lagig (BSK) | WUN-H2-E00-F03b | CEILING | D1 0.001 m | 1116Dfl0000066614/04 | m² | Maler- und Lackierarbeiten | 4 | 0.001 | 0 | 1 | Bekleidung | D1 | 0 | 0 | NEW | 2.5 | AllplanAttributes - ash_lichte Raumhöhe: 2.500000
PVC Bahnenware Holzoptik | WUN-H2-E00-067 | FLOORING | Ku1 0.2 m | 1116Bfl0000065659/01 | m² | Bodenbelagsarbeiten | 1 | 0.2 | 0 | 1 | Bodenfläche | Ku1 | 0 | 0 | NEW | AllplanAttributes - Bezeichnung: PVC Bahnenware Holzoptik; Raumnr. Bauherr: 2.11_A2_02; ash B_Aufbau: B1; ash B_Rutschhemmung: R9
Gipsfaserplatten 2-lagig (BSK) | WUN-H2-E00-067 | CEILING | layer 0.036 m | 1116Dfl0000065658/01 | m² | Trockenbauarbeiten | 1 | 0.036 | 0 | 1 | Deckenfläche |  | 0 | 0 | NEW | 2.5 | AllplanAttributes - Bezeichnung: Gipsfaserplatten 2-lagig (BSK)
Gipsfaserplatten 2-lagig (BSK) | WUN-H2-E00-067 | CEILING | Installationshöhe 0.764 m | 1116Dfl0000065658/02 | m² | Trockenbauarbeiten | 2 | 0.764 | 0 | 1 | Bekleidung | Installationshöhe | 0 | 0 | NEW | 2.5 | Pset_CoveringCommon - FireRating: für korrekte FläVisu; AllplanAttributes - ash_lichte Raumhöhe: 2.500000; OKFF: 0
Kühldecke glatt | WUN-H2-E00-067 | CEILING | H7a 0.1 m | 1116Dfl0000065658/03 | m² | Trockenbauarbeiten | 3 | 0.1 | 0 | 1 | Bekleidung | H7a | 0 | 0 | NEW | 2.5 | AllplanAttributes - Bezeichnung: Kühldecke glatt; ash_lichte Raumhöhe: 2.500000; OKFF: 0; Pset_CoveringCommon - FireRating: -; AcousticRating: -
Gipsfaserplatten 2-lagig (BSK) | WUN-H2-E00-067 | CEILING | D1 0.001 m | 1116Dfl0000065658/04 | m² | Maler- und Lackierarbeiten | 4 | 0.001 | 0 | 1 | Bekleidung | D1 | 0 | 0 | NEW | 2.5 | AllplanAttributes - ash_lichte Raumhöhe: 2.500000; OKFF: 0
PVC Bahnenware Holzoptik | WUN-H2-E00-012 | FLOORING | Ku1 0.2 m | 1116Bfl0000066629/01 | m² | Bodenbelagsarbeiten | 1 | 0.2 | 0 | 1 | Bodenfläche | Ku1 | 0 | 0 | NEW | AllplanAttributes - Bezeichnung: PVC Bahnenware Holzoptik; Raumnr. Bauherr: 2.11_A2_02; ash B_Aufbau: B1; ash B_Rutschhemmung: R9
Gipsfaserplatten 2-lagig (BSK) | WUN-H2-E00-012 | CEILING | layer 0.036 m | 1116Dfl0000066628/01 | m² | Trockenbauarbeiten | 1 | 0.036 | 0 | 1 | Deckenfläche |  | 0 | 0 | NEW | 2.5 | AllplanAttributes - Bezeichnung: Gipsfaserplatten 2-lagig (BSK)
Gipsfaserplatten 2-lagig (BSK) | WUN-H2-E00-012 | CEILING | Installationshöhe 0.764 m | 1116Dfl0000066628/02 | m² | Trockenbauarbeiten | 2 | 0.764 | 0 | 1 | Bekleidung | Installationshöhe | 0 | 0 | NEW | 2.5 | Pset_CoveringCommon - FireRating: für korrekte FläVisu; AllplanAttributes - ash_lichte Raumhöhe: 2.500000; OKFF: 0
Gipsfaserplatten 2-lagig (BSK) | WUN-H2-E00-012 | CEILING | A1 0.1 m | 1116Dfl0000066628/03 | m² | Trockenbauarbeiten | 3 | 0.1 | 0 | 1 | Bekleidung | A1 | 0 | 0 | NEW | 2.5 | Pset_CoveringCommon - FireRating: -; AcousticRating: -; AllplanAttributes - ash_lichte Raumhöhe: 2.500000; OKFF: 0
Gipsfaserplatten 2-lagig (BSK) | WUN-H2-E00-012 | CEILING | D1 0.001 m | 1116Dfl0000066628/04 | m² | Maler- und Lackierarbeiten | 4 | 0.001 | 0 | 1 | Bekleidung | D1 | 0 | 0 | NEW | 2.5 | AllplanAttributes - ash_lichte Raumhöhe: 2.500000; OKFF: 0
PVC Bahnenware Holzoptik | WUN-H2-E00-064 | FLOORING | Ku1 0.2 m | 1116Bfl0000066764/01 | m² | Bodenbelagsarbeiten | 1 | 0.2 | 0 | 1 | Bodenfläche | Ku1 | 0 | 0 | NEW | AllplanAttributes - Bezeichnung: PVC Bahnenware Holzoptik; Raumnr. Bauherr: 2.11_A2_02; ash B_Aufbau: B1; ash B_Rutschhemmung: R9
Gipsfaserplatten 2-lagig (BSK) | WUN-H2-E00-064 | CEILING | layer 0.036 m | 1116Dfl0000066763/01 | m² | Trockenbauarbeiten | 1 | 0.036 | 0 | 1 | Deckenfläche |  | 0 | 0 | NEW | 2.5 | AllplanAttributes - Bezeichnung: Gipsfaserplatten 2-lagig (BSK)
Gipsfaserplatten 2-lagig (BSK) | WUN-H2-E00-064 | CEILING | Installationshöhe 0.764 m | 1116Dfl0000066763/02 | m² | Trockenbauarbeiten | 2 | 0.764 | 0 | 1 | Bekleidung | Installationshöhe | 0 | 0 | NEW | 2.5 | Pset_CoveringCommon - FireRating: für korrekte FläVisu; AllplanAttributes - ash_lichte Raumhöhe: 2.500000; OKFF: 0
Gipsfaserplatten 2-lagig (BSK) | WUN-H2-E00-064 | CEILING | A1 0.1 m | 1116Dfl0000066763/03 | m² | Trockenbauarbeiten | 3 | 0.1 | 0 | 1 | Bekleidung | A1 | 0 | 0 | NEW | 2.5 | Pset_CoveringCommon - FireRating: -; AcousticRating: -; AllplanAttributes - ash_lichte Raumhöhe: 2.500000; OKFF: 0
Gipsfaserplatten 2-lagig (BSK) | WUN-H2-E00-064 | CEILING | D1 0.001 m | 1116Dfl0000066763/04 | m² | Maler- und Lackierarbeiten | 4 | 0.001 | 0 | 1 | Bekleidung | D1 | 0 | 0 | NEW | 2.5 | AllplanAttributes - ash_lichte Raumhöhe: 2.500000; OKFF: 0
PVC Bahnenware Holzoptik | WUN-H2-E00-F09b | FLOORING | Ku1 0.2 m | 1116Bfl0000066586/01 | m² | Bodenbelagsarbeiten | 1 | 0.2 | 0 | 1 | Bodenfläche | Ku1 | 0 | 0 | NEW | AllplanAttributes - Bezeichnung: PVC Bahnenware Holzoptik; Raumnr. Bauherr: 2.11_A2_02; ash B_Aufbau: B1; ash B_Rutschhemmung: R9
Gipsfaserplatten 2-lagig (BSK) | WUN-H2-E00-F09b | CEILING | layer 0.036 m | 1116Dfl0000443805/01 | m² | Trockenbauarbeiten | 1 | 0.036 | 0 | 1 | Deckenfläche |  | 0 | 0 | NEW | 2.5 | AllplanAttributes - Bezeichnung: Gipsfaserplatten 2-lagig (BSK)
Gipsfaserplatten 2-lagig (BSK) | WUN-H2-E00-F09b | CEILING | Installationshöhe 0.714 m | 1116Dfl0000443805/02 | m² | Trockenbauarbeiten | 2 | 0.714 | 0 | 1 | Bekleidung | Installationshöhe | 0 | 0 | NEW | 2.5 | Pset_CoveringCommon - FireRating: für korrekte FläVisu; AllplanAttributes - ash_lichte Raumhöhe: 2.500000
Gipsfaserplatten 2-lagig (BSK) | WUN-H2-E00-F09b | CEILING | Aa 0.15 m | 1116Dfl0000443805/03 | m² | Trockenbauarbeiten | 3 | 0.15 | 0 | 1 | Bekleidung | Aa | 0 | 0 | NEW | 2.5 | AllplanAttributes - ash_lichte Raumhöhe: 2.500000; Pset_CoveringCommon - AcousticRating: -
Gipsfaserplatten 2-lagig (BSK) | WUN-H2-E00-F09b | CEILING | D1 0.001 m | 1116Dfl0000443805/04 | m² | Maler- und Lackierarbeiten | 4 | 0.001 | 0 | 1 | Bekleidung | D1 | 0 | 0 | NEW | 2.5 | AllplanAttributes - ash_lichte Raumhöhe: 2.500000
Gipsfaserplatten 2-lagig (BSK) | WUN-H2-E00-F09b | CEILING | layer 0.036 m | 1116Dfl0000066585/01 | m² | Trockenbauarbeiten | 1 | 0.036 | 0 | 1 | Deckenfläche |  | 0 | 0 | NEW | 2.5 | AllplanAttributes - Bezeichnung: Gipsfaserplatten 2-lagig (BSK)
Gipsfaserplatten 2-lagig (BSK) | WUN-H2-E00-F09b | CEILING | Installationshöhe 0.714 m | 1116Dfl0000066585/02 | m² | Trockenbauarbeiten | 2 | 0.714 | 0 | 1 | Bekleidung | Installationshöhe | 0 | 0 | NEW | 2.5 | Pset_CoveringCommon - FireRating: für korrekte FläVisu; AllplanAttributes - ash_lichte Raumhöhe: 2.500000
Gipsfaserplatten 2-lagig (BSK) | WUN-H2-E00-F09b | CEILING | A1 0.15 m | 1116Dfl0000066585/03 | m² | Trockenbauarbeiten | 3 | 0.15 | 0 | 1 | Bekleidung | A1 | 0 | 0 | NEW | 2.5 | AllplanAttributes - ash_lichte Raumhöhe: 2.500000; Pset_CoveringCommon - AcousticRating: -
Gipsfaserplatten 2-lagig (BSK) | WUN-H2-E00-F09b | CEILING | D1 0.001 m | 1116Dfl0000066585/04 | m² | Maler- und Lackierarbeiten | 4 | 0.001 | 0 | 1 | Bekleidung | D1 | 0 | 0 | NEW | 2.5 | AllplanAttributes - ash_lichte Raumhöhe: 2.500000
PVC Bahnenware Holzoptik | WUN-H2-E00-013 | FLOORING | Ku1 0.2 m | 1116Bfl0000066603/01 | m² | Bodenbelagsarbeiten | 1 | 0.2 | 0 | 1 | Bodenfläche | Ku1 | 0 | 0 | NEW | AllplanAttributes - Bezeichnung: PVC Bahnenware Holzoptik; Raumnr. Bauherr: 2.11_A2_02; ash B_Aufbau: B1; ash B_Rutschhemmung: R9
Gipsfaserplatten 2-lagig (BSK) | WUN-H2-E00-013 | CEILING | layer 0.036 m | 1116Dfl0000872121/01 | m² | Trockenbauarbeiten | 1 | 0.036 | 0 | 1 | Deckenfläche |  | 0 | 0 | NEW | 2.5 | AllplanAttributes - Bezeichnung: Gipsfaserplatten 2-lagig (BSK)
Gipsfaserplatten 2-lagig (BSK) | WUN-H2-E00-013 | CEILING | Installationshöhe 0.714 m | 1116Dfl0000872121/02 | m² | Trockenbauarbeiten | 2 | 0.714 | 0 | 1 | Bekleidung | Installationshöhe | 0 | 0 | NEW | 2.5 | Pset_CoveringCommon - FireRating: für korrekte FläVisu; AllplanAttributes - ash_lichte Raumhöhe: 2.500000
Gipsfaserplatten 2-lagig (BSK) | WUN-H2-E00-013 | CEILING | A1 0.15 m | 1116Dfl0000872121/03 | m² | Trockenbauarbeiten | 3 | 0.15 | 0 | 1 | Bekleidung | A1 | 0 | 0 | NEW | 2.5 | AllplanAttributes - ash_lichte Raumhöhe: 2.500000; Pset_CoveringCommon - AcousticRating: -
Gipsfaserplatten 2-lagig (BSK) | WUN-H2-E00-013 | CEILING | D1 0.001 m | 1116Dfl0000872121/04 | m² | Maler- und Lackierarbeiten | 4 | 0.001 | 0 | 1 | Bekleidung | D1 | 0 | 0 | NEW | 2.5 | AllplanAttributes - ash_lichte Raumhöhe: 2.500000
Gipsfaserplatten 2-lagig (BSK) | WUN-H2-E00-013 | CEILING | layer 0.036 m | 1116Dfl0000889021/01 | m² | Trockenbauarbeiten | 1 | 0.036 | 0 | 1 | Deckenfläche |  | 0 | 0 | NEW | 2.5 | AllplanAttributes - Bezeichnung: Gipsfaserplatten 2-lagig (BSK)
Gipsfaserplatten 2-lagig (BSK) | WUN-H2-E00-013 | CEILING | Installationshöhe 0.714 m | 1116Dfl0000889021/02 | m² | Trockenbauarbeiten | 2 | 0.714 | 0 | 1 | Bekleidung | Installationshöhe | 0 | 0 | NEW | 2.5 | Pset_CoveringCommon - FireRating: für korrekte FläVisu; AllplanAttributes - ash_lichte Raumhöhe: 2.500000
Gipsfaserplatten 2-lagig (BSK) | WUN-H2-E00-013 | CEILING | Aa 0.15 m | 1116Dfl0000889021/03 | m² | Trockenbauarbeiten | 3 | 0.15 | 0 | 1 | Bekleidung | Aa | 0 | 0 | NEW | 2.5 | AllplanAttributes - ash_lichte Raumhöhe: 2.500000; Pset_CoveringCommon - AcousticRating: -
Gipsfaserplatten 2-lagig (BSK) | WUN-H2-E00-013 | CEILING | D1 0.001 m | 1116Dfl0000889021/04 | m² | Maler- und Lackierarbeiten | 4 | 0.001 | 0 | 1 | Bekleidung | D1 | 0 | 0 | NEW | 2.5 | AllplanAttributes - ash_lichte Raumhöhe: 2.500000
Fliesen | WUN-H2-E00-076 | FLOORING | Fl1 0.2 m | 1116Bfl0000065621/01 | m² | Bodenbelagsarbeiten | 1 | 0.2 | 0 | 1 | Bodenfläche | Fl1 | 0 | 0 | NEW | AllplanAttributes - Bezeichnung: Fliesen; Raumnr. Bauherr: 2.11_A2_02; ash B_Aufbau: B2; ash B_Rutschhemmung: R10; ash B_Bewertungsgruppe Barfußbereich: B
Gipsfaserplatten 2-lagig (BSK) | WUN-H2-E00-076 | CEILING | layer 0.036 m | 1116Dfl0000065620/01 | m² | Trockenbauarbeiten | 1 | 0.036 | 0 | 1 | Deckenfläche |  | 0 | 0 | NEW | 2.5 | AllplanAttributes - Bezeichnung: Gipsfaserplatten 2-lagig (BSK)
Gipsfaserplatten 2-lagig (BSK) | WUN-H2-E00-076 | CEILING | Installationshöhe 0.764 m | 1116Dfl0000065620/02 | m² | Trockenbauarbeiten | 2 | 0.764 | 0 | 1 | Bekleidung | Installationshöhe | 0 | 0 | NEW | 2.5 | Pset_CoveringCommon - FireRating: für korrekte FläVisu; AllplanAttributes - ash_lichte Raumhöhe: 2.500000; OKFF: 0
Gipskarton, imprägniert | WUN-H2-E00-076 | CEILING | B 0.1 m | 1116Dfl0000065620/03 | m² | Trockenbauarbeiten | 3 | 0.1 | 0 | 1 | Bekleidung | B | 0 | 0 | NEW | 2.5 | AllplanAttributes - Bezeichnung: Gipskarton, imprägniert; ash_lichte Raumhöhe: 2.500000; OKFF: 0; Pset_CoveringCommon - FireRating: -; AcousticRating: -
Gipsfaserplatten 2-lagig (BSK) | WUN-H2-E00-076 | CEILING | D1 0.001 m | 1116Dfl0000065620/04 | m² | Maler- und Lackierarbeiten | 4 | 0.001 | 0 | 1 | Bekleidung | D1 | 0 | 0 | NEW | 2.5 | AllplanAttributes - ash_lichte Raumhöhe: 2.500000; OKFF: 0
Gipsfaserplatten 2-lagig (BSK) | WUN-H2-E00-040 | CEILING | layer 0.036 m | 1116Dfl0000065636/01 | m² | Trockenbauarbeiten | 1 | 0.036 | 0 | 1 | Deckenfläche |  | 0 | 0 | NEW | 2.5 | AllplanAttributes - Bezeichnung: Gipsfaserplatten 2-lagig (BSK)
Gipsfaserplatten 2-lagig (BSK) | WUN-H2-E00-040 | CEILING | Installationshöhe 0.764 m | 1116Dfl0000065636/02 | m² | Trockenbauarbeiten | 2 | 0.764 | 0 | 1 | Bekleidung | Installationshöhe | 0 | 0 | NEW | 2.5 | Pset_CoveringCommon - FireRating: für korrekte FläVisu; AllplanAttributes - ash_lichte Raumhöhe: (3400-36+764+100)/1000-0
Rasterdecke | WUN-H2-E00-040 | CEILING | E3 0.1 m | 1116Dfl0000065636/03 | m² | Trockenbauarbeiten | 3 | 0.1 | 0 | 1 | Bekleidung | E3 | 0 | 0 | NEW | 2.5 | AllplanAttributes - Bezeichnung: Rasterdecke; ash_lichte Raumhöhe: (3400-36+764+100)/1000-0; Pset_CoveringCommon - FireRating: -; AcousticRating: -
PVC Bahnenware Uni | WUN-H2-E00-040 | FLOORING | Ku2 0.2 m | 1116Bfl0000065635/01 | m² | Bodenbelagsarbeiten | 1 | 0.2 | 0 | 1 | Bodenfläche | Ku2 | 0 | 0 | NEW | AllplanAttributes - Bezeichnung: PVC Bahnenware Uni; Raumnr. Bauherr: 2.11_A2_02; ash B_Aufbau: B1; ash B_Rutschhemmung: R9
Gipsfaserplatten 2-lagig (BSK) | WUN-H2-E00-032 | CEILING | layer 0.036 m | 1116Dfl0000065653/01 | m² | Trockenbauarbeiten | 1 | 0.036 | 0 | 1 | Deckenfläche |  | 0 | 0 | NEW | 2.5 | AllplanAttributes - Bezeichnung: Gipsfaserplatten 2-lagig (BSK)
Gipsfaserplatten 2-lagig (BSK) | WUN-H2-E00-032 | CEILING | Installationshöhe 0.764 m | 1116Dfl0000065653/02 | m² | Trockenbauarbeiten | 2 | 0.764 | 0 | 1 | Bekleidung | Installationshöhe | 0 | 0 | NEW | 2.5 | Pset_CoveringCommon - FireRating: für korrekte FläVisu; AllplanAttributes - ash_lichte Raumhöhe: (3400-36+764+100)/1000-0
Rasterdecke | WUN-H2-E00-032 | CEILING | E3 0.1 m | 1116Dfl0000065653/03 | m² | Trockenbauarbeiten | 3 | 0.1 | 0 | 1 | Bekleidung | E3 | 0 | 0 | NEW | 2.5 | AllplanAttributes - Bezeichnung: Rasterdecke; ash_lichte Raumhöhe: (3400-36+764+100)/1000-0; Pset_CoveringCommon - FireRating: -; AcousticRating: -
PVC Bahnenware Uni | WUN-H2-E00-032 | FLOORING | Ku2 0.2 m | 1116Bfl0000065654/01 | m² | Bodenbelagsarbeiten | 1 | 0.2 | 0 | 1 | Bodenfläche | Ku2 | 0 | 0 | NEW | AllplanAttributes - Bezeichnung: PVC Bahnenware Uni; Raumnr. Bauherr: 2.11_A2_02; ash B_Aufbau: B1; ash B_Rutschhemmung: R9
Gipsfaserplatten 2-lagig (BSK) | WUN-H2-E00-031 | CEILING | layer 0.036 m | 1116Dfl0000065396/01 | m² | Trockenbauarbeiten | 1 | 0.036 | 0 | 1 | Deckenfläche |  | 0 | 0 | NEW | 2.5 | AllplanAttributes - Bezeichnung: Gipsfaserplatten 2-lagig (BSK)
Gipsfaserplatten 2-lagig (BSK) | WUN-H2-E00-031 | CEILING | Installationshöhe 0.764 m | 1116Dfl0000065396/02 | m² | Trockenbauarbeiten | 2 | 0.764 | 0 | 1 | Bekleidung | Installationshöhe | 0 | 0 | NEW | 2.5 | Pset_CoveringCommon - FireRating: für korrekte FläVisu; AllplanAttributes - ash_lichte Raumhöhe: (3400-36+764+100)/1000-0
Rasterdecke | WUN-H2-E00-031 | CEILING | E3 0.1 m | 1116Dfl0000065396/03 | m² | Trockenbauarbeiten | 3 | 0.1 | 0 | 1 | Bekleidung | E3 | 0 | 0 | NEW | 2.5 | AllplanAttributes - Bezeichnung: Rasterdecke; ash_lichte Raumhöhe: (3400-36+764+100)/1000-0; Pset_CoveringCommon - FireRating: -; AcousticRating: -
Fliesen | WUN-H2-E00-031 | FLOORING | Fl1 0.2 m | 1116Bfl0000065395/01 | m² | Bodenbelagsarbeiten | 1 | 0.2 | 0 | 1 | Bodenfläche | Fl1 | 0 | 0 | NEW | AllplanAttributes - Bezeichnung: Fliesen; Raumnr. Bauherr: 2.11_A2_02; ash B_Aufbau: B2; ash B_Rutschhemmung: R10
Fliesen | WUN-H2-E00-039 | FLOORING | Fl1 0.2 m | 1116Bfl0000065641/01 | m² | Bodenbelagsarbeiten | 1 | 0.2 | 0 | 1 | Bodenfläche | Fl1 | 0 | 0 | NEW | AllplanAttributes - Bezeichnung: Fliesen; Raumnr. Bauherr: 2.11_A2_02; ash B_Aufbau: B2; ash B_Rutschhemmung: R10
Fliesen Mosaik | WUN-H2-E00-039 | FLOORING | Fl2 0.2 m | 1116Bfl0001165410/01 | m² | Bodenbelagsarbeiten | 1 | 0.2 | 0 | 1 | Bodenfläche | Fl2 | 0 | 0 | NEW | AllplanAttributes - Bezeichnung: Fliesen Mosaik; Raumnr. Bauherr: 2.11_A2_02; ash B_Aufbau: B3; ash B_Rutschhemmung: R10; ash B_Bewertungsgruppe Barfußbereich: B
Gipsfaserplatten 2-lagig (BSK) | WUN-H2-E00-039 | CEILING | layer 0.036 m | 1116Dfl0000065640/01 | m² | Trockenbauarbeiten | 1 | 0.036 | 0 | 1 | Deckenfläche |  | 0 | 0 | NEW | 2.5 | AllplanAttributes - Bezeichnung: Gipsfaserplatten 2-lagig (BSK)
Gipsfaserplatten 2-lagig (BSK) | WUN-H2-E00-039 | CEILING | Installationshöhe 0.764 m | 1116Dfl0000065640/02 | m² | Trockenbauarbeiten | 2 | 0.764 | 0 | 1 | Bekleidung | Installationshöhe | 0 | 0 | NEW | 2.5 | Pset_CoveringCommon - FireRating: für korrekte FläVisu; AllplanAttributes - ash_lichte Raumhöhe: 2.500000; OKFF: 0
Gipskarton, imprägniert | WUN-H2-E00-039 | CEILING | B 0.1 m | 1116Dfl0000065640/03 | m² | Trockenbauarbeiten | 3 | 0.1 | 0 | 1 | Bekleidung | B | 0 | 0 | NEW | 2.5 | AllplanAttributes - Bezeichnung: Gipskarton, imprägniert; ash_lichte Raumhöhe: 2.500000; OKFF: 0; Pset_CoveringCommon - FireRating: -; AcousticRating: -
Gipsfaserplatten 2-lagig (BSK) | WUN-H2-E00-039 | CEILING | D1 0.001 m | 1116Dfl0000065640/04 | m² | Maler- und Lackierarbeiten | 4 | 0.001 | 0 | 1 | Bekleidung | D1 | 0 | 0 | NEW | 2.5 | AllplanAttributes - ash_lichte Raumhöhe: 2.500000; OKFF: 0
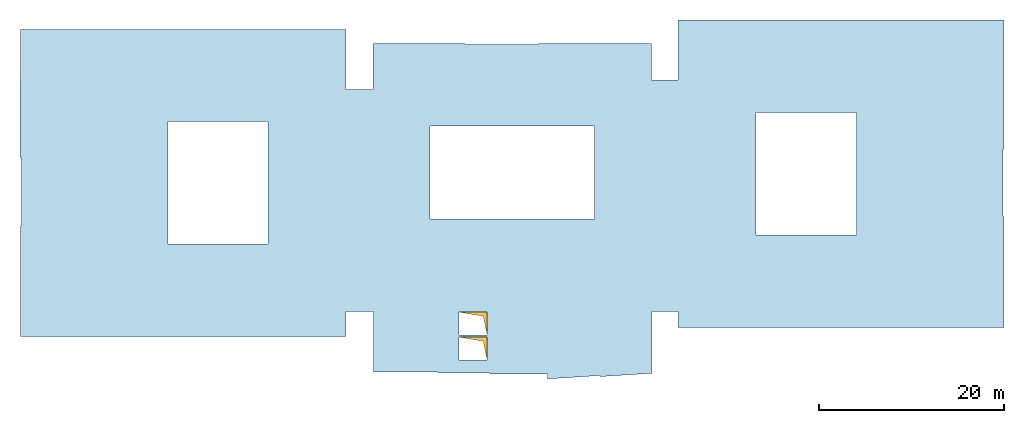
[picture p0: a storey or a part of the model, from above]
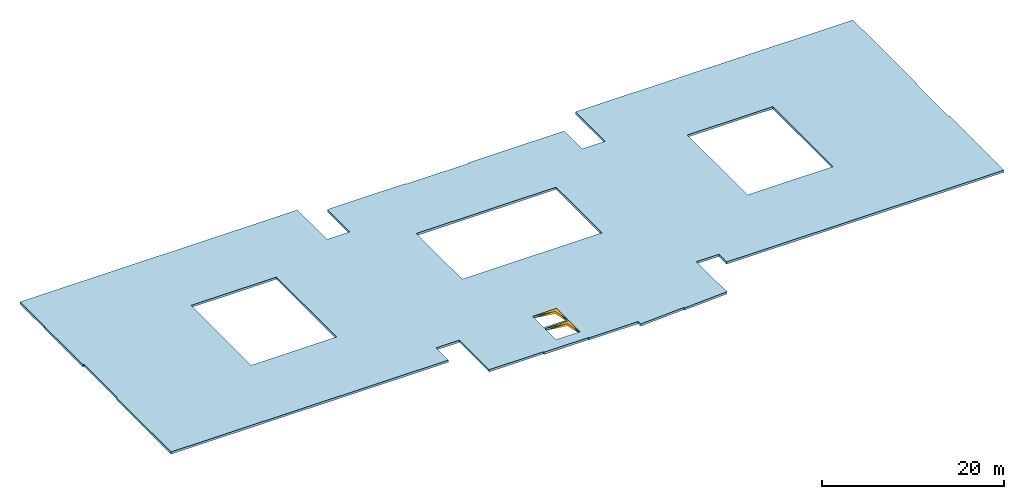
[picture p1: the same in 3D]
Properties of the parts of a building model (IFC4), part 20 of 80

# IfcCovering (3945)
Name | In | PredefinedType | Material | Allright_Bauteil_ID | Abrechnungsart | Gewerk | Schichtnummer | Schichtdicke (m) | Dicke (m) | Faktor | Objektname | AllplanAttributes, Material | Bezugshöhe | Deltahöhe | Status | D_lichte Raumhöhe [Zahl] (m)
Gipsfaserplatten 2-lagig (BSK) | WUN-H2-E00-038 | CEILING | layer 0.036 m | 1116Dfl0000065646/01 | m² | Trockenbauarbeiten | 1 | 0.036 | 0 | 1 | Deckenfläche |  | 0 | 0 | NEW | 2.5 | AllplanAttributes - Bezeichnung: Gipsfaserplatten 2-lagig (BSK)
Gipsfaserplatten 2-lagig (BSK) | WUN-H2-E00-038 | CEILING | Installationshöhe 0.764 m | 1116Dfl0000065646/02 | m² | Trockenbauarbeiten | 2 | 0.764 | 0 | 1 | Bekleidung | Installationshöhe | 0 | 0 | NEW | 2.5 | Pset_CoveringCommon - FireRating: für korrekte FläVisu; AllplanAttributes - ash_lichte Raumhöhe: (3400-36+764+100)/1000-0
Rasterdecke | WUN-H2-E00-038 | CEILING | E3 0.1 m | 1116Dfl0000065646/03 | m² | Trockenbauarbeiten | 3 | 0.1 | 0 | 1 | Bekleidung | E3 | 0 | 0 | NEW | 2.5 | AllplanAttributes - Bezeichnung: Rasterdecke; ash_lichte Raumhöhe: (3400-36+764+100)/1000-0; Pset_CoveringCommon - FireRating: -; AcousticRating: -
PVC Bahnenware Uni | WUN-H2-E00-038 | FLOORING | Ku2 0.2 m | 1116Bfl0000065645/01 | m² | Bodenbelagsarbeiten | 1 | 0.2 | 0 | 1 | Bodenfläche | Ku2 | 0 | 0 | NEW | AllplanAttributes - Bezeichnung: PVC Bahnenware Uni; Raumnr. Bauherr: 2.11_A2_02; ash B_Aufbau: B1; ash B_Rutschhemmung: R9
PVC Bahnenware Holzoptik | WUN-H2-E00-010 | FLOORING | Ku1 0.2 m | 1116Bfl0000065584/01 | m² | Bodenbelagsarbeiten | 1 | 0.2 | 0 | 1 | Bodenfläche | Ku1 | 0 | 0 | NEW | AllplanAttributes - Bezeichnung: PVC Bahnenware Holzoptik; Raumnr. Bauherr: 2.11_A2_02; ash B_Aufbau: B1; ash B_Rutschhemmung: R9
Gipsfaserplatten 2-lagig (BSK) | WUN-H2-E00-010 | CEILING | layer 0.036 m | 1116Dfl0000065909/01 | m² | Trockenbauarbeiten | 1 | 0.036 | 0 | 1 | Deckenfläche |  | 0 | 0 | NEW | 2.5 | AllplanAttributes - Bezeichnung: Gipsfaserplatten 2-lagig (BSK)
Gipsfaserplatten 2-lagig (BSK) | WUN-H2-E00-010 | CEILING | Installationshöhe 0.764 m | 1116Dfl0000065909/02 | m² | Trockenbauarbeiten | 2 | 0.764 | 0 | 1 | Bekleidung | Installationshöhe | 0 | 0 | NEW | 2.5 | Pset_CoveringCommon - FireRating: für korrekte FläVisu; AllplanAttributes - ash_lichte Raumhöhe: 2.500000; OKFF: 0
Kühldecke glatt | WUN-H2-E00-010 | CEILING | H7a 0.1 m | 1116Dfl0000065909/03 | m² | Trockenbauarbeiten | 3 | 0.1 | 0 | 1 | Bekleidung | H7a | 0 | 0 | NEW | 2.5 | AllplanAttributes - Bezeichnung: Kühldecke glatt; ash_lichte Raumhöhe: 2.500000; OKFF: 0; Pset_CoveringCommon - FireRating: -; AcousticRating: -
Gipsfaserplatten 2-lagig (BSK) | WUN-H2-E00-010 | CEILING | D1 0.001 m | 1116Dfl0000065909/04 | m² | Maler- und Lackierarbeiten | 4 | 0.001 | 0 | 1 | Bekleidung | D1 | 0 | 0 | NEW | 2.5 | AllplanAttributes - ash_lichte Raumhöhe: 2.500000; OKFF: 0
Gipsfaserplatten 2-lagig (BSK) | WUN-H2-E00-010 | CEILING | layer 0.036 m | 1116Dfl0000940827/01 | m² | Trockenbauarbeiten | 1 | 0.036 | 0 | 1 | Deckenfläche |  | 0 | 0 | NEW | 2.5 | AllplanAttributes - Bezeichnung: Gipsfaserplatten 2-lagig (BSK)
Gipsfaserplatten 2-lagig (BSK) | WUN-H2-E00-010 | CEILING | Installationshöhe 0.764 m | 1116Dfl0000940827/02 | m² | Trockenbauarbeiten | 2 | 0.764 | 0 | 1 | Bekleidung | Installationshöhe | 0 | 0 | NEW | 2.5 | Pset_CoveringCommon - FireRating: für korrekte FläVisu; AllplanAttributes - ash_lichte Raumhöhe: 2.500000; OKFF: 0
Kühldecke gelocht | WUN-H2-E00-010 | CEILING | H7b 0.1 m | 1116Dfl0000940827/03 | m² | Trockenbauarbeiten | 3 | 0.1 | 0 | 1 | Bekleidung | H7b | 0 | 0 | NEW | 2.5 | AllplanAttributes - Bezeichnung: Kühldecke gelocht; ash_lichte Raumhöhe: 2.500000; OKFF: 0; Pset_CoveringCommon - FireRating: -; AcousticRating: -
Gipsfaserplatten 2-lagig (BSK) | WUN-H2-E00-010 | CEILING | D1 0.001 m | 1116Dfl0000940827/04 | m² | Maler- und Lackierarbeiten | 4 | 0.001 | 0 | 1 | Bekleidung | D1 | 0 | 0 | NEW | 2.5 | AllplanAttributes - ash_lichte Raumhöhe: 2.500000; OKFF: 0
Gipsfaserplatten 2-lagig (BSK) | WUN-H2-E00-001 | CEILING | layer 0.036 m | 1116Dfl0000065599/01 | m² | Trockenbauarbeiten | 1 | 0.036 | 0 | 1 | Deckenfläche |  | 0 | 0 | NEW | 2.5 | AllplanAttributes - Bezeichnung: Gipsfaserplatten 2-lagig (BSK)
Gipsfaserplatten 2-lagig (BSK) | WUN-H2-E00-001 | CEILING | Installationshöhe 0.764 m | 1116Dfl0000065599/02 | m² | Trockenbauarbeiten | 2 | 0.764 | 0 | 1 | Bekleidung | Installationshöhe | 0 | 0 | NEW | 2.5 | Pset_CoveringCommon - FireRating: für korrekte FläVisu; AllplanAttributes - ash_lichte Raumhöhe: (3400-36+764+100)/1000-0
Rasterdecke | WUN-H2-E00-001 | CEILING | E3 0.1 m | 1116Dfl0000065599/03 | m² | Trockenbauarbeiten | 3 | 0.1 | 0 | 1 | Bekleidung | E3 | 0 | 0 | NEW | 2.5 | AllplanAttributes - Bezeichnung: Rasterdecke; ash_lichte Raumhöhe: (3400-36+764+100)/1000-0; Pset_CoveringCommon - FireRating: -; AcousticRating: -
PVC Bahnenware Uni | WUN-H2-E00-001 | FLOORING | Ku2 0.2 m | 1116Bfl0000065598/01 | m² | Bodenbelagsarbeiten | 1 | 0.2 | 0 | 1 | Bodenfläche | Ku2 | 0 | 0 | NEW | AllplanAttributes - Bezeichnung: PVC Bahnenware Uni; Raumnr. Bauherr: 2.11_A2_02; ash B_Aufbau: B1; ash B_Rutschhemmung: R9
Fliesen | WUN-H2-E00-052 | FLOORING | Fl1 0.2 m | 1116Bfl0000069154/01 | m² | Bodenbelagsarbeiten | 1 | 0.2 | 0 | 1 | Bodenfläche | Fl1 | 0 | 0 | AllplanAttributes - Bezeichnung: Fliesen; Raumnr. Bauherr: 2.11_A2_02; ash B_Aufbau: B2; ash B_Rutschhemmung: R10
Gipsfaserplatten 2-lagig (BSK) | WUN-H2-E00-052 | CEILING | layer 0.036 m | 1116Dfl0000069153/01 | m² | Trockenbauarbeiten | 1 | 0.036 | 0 | 1 | Deckenfläche |  | 0 | 0 |  | 2.5 | AllplanAttributes - Bezeichnung: Gipsfaserplatten 2-lagig (BSK)
 | WUN-H2-E00-052 | CEILING | Installationshöhe 0.764 m | 1116Dfl0000069153/02 | m² | Trockenbauarbeiten | 2 | 0.764 | 0 | 1 | Bekleidung | Installationshöhe | 0 | 0 |  | 2.5 | Pset_CoveringCommon - FireRating: für korrekte FläVisu; AllplanAttributes - ash_lichte Raumhöhe: 2.500000; OKFF: 0
Gipskarton, imprägniert | WUN-H2-E00-052 | CEILING | B 0.1 m | 1116Dfl0000069153/03 | m² | Trockenbauarbeiten | 3 | 0.1 | 0 | 1 | Bekleidung | B | 0 | 0 |  | 2.5 | AllplanAttributes - Bezeichnung: Gipskarton, imprägniert; ash_lichte Raumhöhe: 2.500000; OKFF: 0; Pset_CoveringCommon - FireRating: -; AcousticRating: -
 | WUN-H2-E00-052 | CEILING | D1 0.001 m | 1116Dfl0000069153/04 | m² | Maler- und Lackierarbeiten | 4 | 0.001 | 0 | 1 | Bekleidung | D1 | 0 | 0 | NEW | 2.5 | AllplanAttributes - ash_lichte Raumhöhe: 2.500000; OKFF: 0
Fliesen | WUN-H2-E00-052a | FLOORING | Fl1 0.2 m | 1116Bfl0000065600/01 | m² | Bodenbelagsarbeiten | 1 | 0.2 | 0 | 1 | Bodenfläche | Fl1 | 0 | 0 | AllplanAttributes - Bezeichnung: Fliesen; Raumnr. Bauherr: 2.11_A2_02; ash B_Aufbau: B2; ash B_Rutschhemmung: R10
Gipsfaserplatten 2-lagig (BSK) | WUN-H2-E00-052a | CEILING | layer 0.036 m | 1116Dfl0000065601/01 | m² | Trockenbauarbeiten | 1 | 0.036 | 0 | 1 | Deckenfläche |  | 0 | 0 |  | 2.5 | AllplanAttributes - Bezeichnung: Gipsfaserplatten 2-lagig (BSK)
 | WUN-H2-E00-052a | CEILING | Installationshöhe 0.764 m | 1116Dfl0000065601/02 | m² | Trockenbauarbeiten | 2 | 0.764 | 0 | 1 | Bekleidung | Installationshöhe | 0 | 0 |  | 2.5 | Pset_CoveringCommon - FireRating: für korrekte FläVisu; AllplanAttributes - ash_lichte Raumhöhe: 2.500000; OKFF: 0
Gipskarton, imprägniert | WUN-H2-E00-052a | CEILING | B 0.1 m | 1116Dfl0000065601/03 | m² | Trockenbauarbeiten | 3 | 0.1 | 0 | 1 | Bekleidung | B | 0 | 0 |  | 2.5 | AllplanAttributes - Bezeichnung: Gipskarton, imprägniert; ash_lichte Raumhöhe: 2.500000; OKFF: 0; Pset_CoveringCommon - FireRating: -; AcousticRating: -
 | WUN-H2-E00-052a | CEILING | D1 0.001 m | 1116Dfl0000065601/04 | m² | Maler- und Lackierarbeiten | 4 | 0.001 | 0 | 1 | Bekleidung | D1 | 0 | 0 | NEW | 2.5 | AllplanAttributes - ash_lichte Raumhöhe: 2.500000; OKFF: 0
Gipsfaserplatten 2-lagig (BSK) | WUN-H2-E00-026 | CEILING | layer 0.036 m | 1116Dfl0000065245/01 | m² | Trockenbauarbeiten | 1 | 0.036 | 0 | 1 | Deckenfläche |  | 0 | 0 | NEW | 2.5 | AllplanAttributes - Bezeichnung: Gipsfaserplatten 2-lagig (BSK)
Gipsfaserplatten 2-lagig (BSK) | WUN-H2-E00-026 | CEILING | Installationshöhe 0.764 m | 1116Dfl0000065245/02 | m² | Trockenbauarbeiten | 2 | 0.764 | 0 | 1 | Bekleidung | Installationshöhe | 0 | 0 | NEW | 2.5 | Pset_CoveringCommon - FireRating: für korrekte FläVisu; AllplanAttributes - ash_lichte Raumhöhe: (3400-36+764+100)/1000-0
Rasterdecke | WUN-H2-E00-026 | CEILING | E3 0.1 m | 1116Dfl0000065245/03 | m² | Trockenbauarbeiten | 3 | 0.1 | 0 | 1 | Bekleidung | E3 | 0 | 0 | NEW | 2.5 | AllplanAttributes - Bezeichnung: Rasterdecke; ash_lichte Raumhöhe: (3400-36+764+100)/1000-0; Pset_CoveringCommon - FireRating: -; AcousticRating: -
PVC Bahnenware Uni | WUN-H2-E00-026 | FLOORING | Ku2 0.2 m | 1116Bfl0000065244/01 | m² | Bodenbelagsarbeiten | 1 | 0.2 | 0 | 1 | Bodenfläche | Ku2 | 0 | 0 | NEW | AllplanAttributes - Bezeichnung: PVC Bahnenware Uni; Raumnr. Bauherr: 2.11_A2_02; ash B_Aufbau: B1; ash B_Rutschhemmung: R9
Gipsfaserplatten 2-lagig (BSK) | WUN-H2-E00-075 | CEILING | layer 0.036 m | 1116Dfl0000065615/01 | m² | Trockenbauarbeiten | 1 | 0.036 | 0 | 1 | Deckenfläche |  | 0 | 0 | NEW | 2.5 | AllplanAttributes - Bezeichnung: Gipsfaserplatten 2-lagig (BSK)
Gipsfaserplatten 2-lagig (BSK) | WUN-H2-E00-075 | CEILING | Installationshöhe 0.764 m | 1116Dfl0000065615/02 | m² | Trockenbauarbeiten | 2 | 0.764 | 0 | 1 | Bekleidung | Installationshöhe | 0 | 0 | NEW | 2.5 | Pset_CoveringCommon - FireRating: für korrekte FläVisu; AllplanAttributes - ash_lichte Raumhöhe: (3400-36+764+100)/1000-0
Rasterdecke | WUN-H2-E00-075 | CEILING | E3 0.1 m | 1116Dfl0000065615/03 | m² | Trockenbauarbeiten | 3 | 0.1 | 0 | 1 | Bekleidung | E3 | 0 | 0 | NEW | 2.5 | AllplanAttributes - Bezeichnung: Rasterdecke; ash_lichte Raumhöhe: (3400-36+764+100)/1000-0; Pset_CoveringCommon - FireRating: -; AcousticRating: -
PVC Bahnenware Uni | WUN-H2-E00-075 | FLOORING | Ku2 0.2 m | 1116Bfl0000065616/01 | m² | Bodenbelagsarbeiten | 1 | 0.2 | 0 | 1 | Bodenfläche | Ku2 | 0 | 0 | NEW | AllplanAttributes - Bezeichnung: PVC Bahnenware Uni; Raumnr. Bauherr: 2.11_A2_02; ash B_Aufbau: B1; ash B_Rutschhemmung: R9
Gipsfaserplatten 2-lagig (BSK) | WUN-H2-E00-089 | CEILING | layer 0.036 m | 1116Dfl0000065411/01 | m² | Trockenbauarbeiten | 1 | 0.036 | 0 | 1 | Deckenfläche |  | 0 | 0 | NEW | 2.5 | AllplanAttributes - Bezeichnung: Gipsfaserplatten 2-lagig (BSK)
Gipsfaserplatten 2-lagig (BSK) | WUN-H2-E00-089 | CEILING | Installationshöhe 0.764 m | 1116Dfl0000065411/02 | m² | Trockenbauarbeiten | 2 | 0.764 | 0 | 1 | Bekleidung | Installationshöhe | 0 | 0 | NEW | 2.5 | Pset_CoveringCommon - FireRating: für korrekte FläVisu; AllplanAttributes - ash_lichte Raumhöhe: (3400-36+764+100)/1000-0
Rasterdecke | WUN-H2-E00-089 | CEILING | E3 0.1 m | 1116Dfl0000065411/03 | m² | Trockenbauarbeiten | 3 | 0.1 | 0 | 1 | Bekleidung | E3 | 0 | 0 | NEW | 2.5 | AllplanAttributes - Bezeichnung: Rasterdecke; ash_lichte Raumhöhe: (3400-36+764+100)/1000-0; Pset_CoveringCommon - FireRating: -; AcousticRating: -
PVC Bahnenware Uni | WUN-H2-E00-089 | FLOORING | Ku2 0.2 m | 1116Bfl0000065410/01 | m² | Bodenbelagsarbeiten | 1 | 0.2 | 0 | 1 | Bodenfläche | Ku2 | 0 | 0 | NEW | AllplanAttributes - Bezeichnung: PVC Bahnenware Uni; Raumnr. Bauherr: 2.11_A2_02; ash B_Aufbau: B1; ash B_Rutschhemmung: R9
 | WUN-H2-E00-L01 | CEILING | Installationshöhe 0.185 m | 1116Dfl0000934732/01 | m² | Trockenbauarbeiten | 1 | 0.185 | 0 | 1 | Bekleidung | Installationshöhe | 0 | 0 | NEW | 3.1 | Pset_CoveringCommon - FireRating: für korrekte FläVisu; AllplanAttributes - ash_lichte Raumhöhe: (3320-185+45)/1000-0; OKFF: 0
Abhangdecke | WUN-H2-E00-L01 | CEILING | - 0.045 m | 1116Dfl0000934732/02 | m² | Trockenbauarbeiten | 2 | 0.045 | 0 | 1 | Bekleidung | - | 0 | 0 | NEW | 3.1 | AllplanAttributes - Bezeichnung: Abhangdecke; ash_lichte Raumhöhe: (3320-185+45)/1000-0; OKFF: 0; Pset_CoveringCommon - FireRating: -; AcousticRating: -
Betonplatten 40x40x5 | WUN-H2-E00-L01 | FLOORING | BP1 0.05 m | 1116Bfl0000934733/01 | m² |  | 1 | 0.05 | 0 | 1 | Bodenfläche | BP1 | 0 | 0 | NEW | AllplanAttributes - Bezeichnung: Betonplatten 40x40x5
 | WUN-H2-E00-L02 | CEILING | Installationshöhe 0.185 m | 1116Dfl0000934791/01 | m² | Trockenbauarbeiten | 1 | 0.185 | 0 | 1 | Bekleidung | Installationshöhe | 0 | 0 | NEW | 3.1 | Pset_CoveringCommon - FireRating: für korrekte FläVisu; AllplanAttributes - ash_lichte Raumhöhe: (3320-185+45)/1000-0; OKFF: 0
 | WUN-H2-E00-L02 | CEILING | - 0.045 m | 1116Dfl0000934791/02 | m² | Trockenbauarbeiten | 2 | 0.045 | 0 | 1 | Bekleidung | - | 0 | 0 | NEW | 3.1 | Pset_CoveringCommon - FireRating: -; AcousticRating: -; AllplanAttributes - ash_lichte Raumhöhe: (3320-185+45)/1000-0; OKFF: 0
Betonplatten 40x40x5 | WUN-H2-E00-L02 | FLOORING | BP1 0.05 m | 1116Bfl0000934792/01 | m² |  | 1 | 0.05 | 0 | 1 | Bodenfläche | BP1 | 0 | 0 | NEW | AllplanAttributes - Bezeichnung: Betonplatten 40x40x5
PVC Bahnenware Holzoptik | WUN-H2-E00-037 | FLOORING | Ku1 0.2 m | 1116Bfl0000065332/01 | m² | Bodenbelagsarbeiten | 1 | 0.2 | 0 | 1 | Bodenfläche | Ku1 | 0 | 0 | NEW | AllplanAttributes - Bezeichnung: PVC Bahnenware Holzoptik; Raumnr. Bauherr: 2.11_A2_02; ash B_Aufbau: B1; ash B_Rutschhemmung: R9
Gipsfaserplatten 2-lagig (BSK) | WUN-H2-E00-037 | CEILING | layer 0.036 m | 1116Dfl0000430896/01 | m² | Trockenbauarbeiten | 1 | 0.036 | 0 | 1 | Deckenfläche |  | 0 | 0 | NEW | 2.5 | AllplanAttributes - Bezeichnung: Gipsfaserplatten 2-lagig (BSK)
Gipsfaserplatten 2-lagig (BSK) | WUN-H2-E00-037 | CEILING | Installationshöhe 0.714 m | 1116Dfl0000430896/02 | m² | Trockenbauarbeiten | 2 | 0.714 | 0 | 1 | Bekleidung | Installationshöhe | 0 | 0 | NEW | 2.5 | Pset_CoveringCommon - FireRating: für korrekte FläVisu; AllplanAttributes - ash_lichte Raumhöhe: 2.500000; OKFF: 0
Gipsfaserplatten 2-lagig (BSK) | WUN-H2-E00-037 | CEILING | Aa 0.15 m | 1116Dfl0000430896/03 | m² | Trockenbauarbeiten | 3 | 0.15 | 0 | 1 | Bekleidung | Aa | 0 | 0 | NEW | 2.5 | Pset_CoveringCommon - FireRating: -; AcousticRating: -; AllplanAttributes - ash_lichte Raumhöhe: 2.500000; OKFF: 0
Gipsfaserplatten 2-lagig (BSK) | WUN-H2-E00-037 | CEILING | D1 0.001 m | 1116Dfl0000430896/04 | m² | Maler- und Lackierarbeiten | 4 | 0.001 | 0 | 1 | Bekleidung | D1 | 0 | 0 | NEW | 2.5 | AllplanAttributes - ash_lichte Raumhöhe: 2.500000; OKFF: 0
Gipsfaserplatten 2-lagig (BSK) | WUN-H2-E00-037 | CEILING | layer 0.036 m | 1116Dfl0000065975/01 | m² | Trockenbauarbeiten | 1 | 0.036 | 0 | 1 | Deckenfläche |  | 0 | 0 | NEW | 2.5 | AllplanAttributes - Bezeichnung: Gipsfaserplatten 2-lagig (BSK)
Gipsfaserplatten 2-lagig (BSK) | WUN-H2-E00-037 | CEILING | Installationshöhe 0.714 m | 1116Dfl0000065975/02 | m² | Trockenbauarbeiten | 2 | 0.714 | 0 | 1 | Bekleidung | Installationshöhe | 0 | 0 | NEW | 2.5 | Pset_CoveringCommon - FireRating: für korrekte FläVisu; AllplanAttributes - ash_lichte Raumhöhe: 2.500000; OKFF: 0
Gipsfaserplatten 2-lagig (BSK) | WUN-H2-E00-037 | CEILING | A1 0.15 m | 1116Dfl0000065975/03 | m² | Trockenbauarbeiten | 3 | 0.15 | 0 | 1 | Bekleidung | A1 | 0 | 0 | NEW | 2.5 | Pset_CoveringCommon - FireRating: -; AcousticRating: -; AllplanAttributes - ash_lichte Raumhöhe: 2.500000; OKFF: 0
Gipsfaserplatten 2-lagig (BSK) | WUN-H2-E00-037 | CEILING | D1 0.001 m | 1116Dfl0000065975/04 | m² | Maler- und Lackierarbeiten | 4 | 0.001 | 0 | 1 | Bekleidung | D1 | 0 | 0 | NEW | 2.5 | AllplanAttributes - ash_lichte Raumhöhe: 2.500000; OKFF: 0
PVC Bahnenware Holzoptik | WUN-H2-E00-036 | FLOORING | Ku1 0.2 m | 1116Bfl0000066673/01 | m² | Bodenbelagsarbeiten | 1 | 0.2 | 0 | 1 | Bodenfläche | Ku1 | 0 | 0 | NEW | AllplanAttributes - Bezeichnung: PVC Bahnenware Holzoptik; Raumnr. Bauherr: 2.11_A2_02; ash B_Aufbau: B1; ash B_Rutschhemmung: R9
Gipsfaserplatten 2-lagig (BSK) | WUN-H2-E00-036 | CEILING | layer 0.036 m | 1116Dfl0000066689/01 | m² | Trockenbauarbeiten | 1 | 0.036 | 0 | 1 | Deckenfläche |  | 0 | 0 | NEW | 2.5 | AllplanAttributes - Bezeichnung: Gipsfaserplatten 2-lagig (BSK)
Gipsfaserplatten 2-lagig (BSK) | WUN-H2-E00-036 | CEILING | Installationshöhe 0.714 m | 1116Dfl0000066689/02 | m² | Trockenbauarbeiten | 2 | 0.714 | 0 | 1 | Bekleidung | Installationshöhe | 0 | 0 | NEW | 2.5 | Pset_CoveringCommon - FireRating: für korrekte FläVisu; AllplanAttributes - ash_lichte Raumhöhe: 2.500000; OKFF: 0
Gipsfaserplatten 2-lagig (BSK) | WUN-H2-E00-036 | CEILING | A1 0.15 m | 1116Dfl0000066689/03 | m² | Trockenbauarbeiten | 3 | 0.15 | 0 | 1 | Bekleidung | A1 | 0 | 0 | NEW | 2.5 | Pset_CoveringCommon - FireRating: -; AcousticRating: -; AllplanAttributes - ash_lichte Raumhöhe: 2.500000; OKFF: 0
Gipsfaserplatten 2-lagig (BSK) | WUN-H2-E00-036 | CEILING | D1 0.001 m | 1116Dfl0000066689/04 | m² | Maler- und Lackierarbeiten | 4 | 0.001 | 0 | 1 | Bekleidung | D1 | 0 | 0 | NEW | 2.5 | AllplanAttributes - ash_lichte Raumhöhe: 2.500000; OKFF: 0
Gipsfaserplatten 2-lagig (BSK) | WUN-H2-E00-036 | CEILING | layer 0.036 m | 1116Dfl0000431476/01 | m² | Trockenbauarbeiten | 1 | 0.036 | 0 | 1 | Deckenfläche |  | 0 | 0 | NEW | 2.5 | AllplanAttributes - Bezeichnung: Gipsfaserplatten 2-lagig (BSK)
Gipsfaserplatten 2-lagig (BSK) | WUN-H2-E00-036 | CEILING | Installationshöhe 0.714 m | 1116Dfl0000431476/02 | m² | Trockenbauarbeiten | 2 | 0.714 | 0 | 1 | Bekleidung | Installationshöhe | 0 | 0 | NEW | 2.5 | Pset_CoveringCommon - FireRating: für korrekte FläVisu; AllplanAttributes - ash_lichte Raumhöhe: 2.500000; OKFF: 0
Gipsfaserplatten 2-lagig (BSK) | WUN-H2-E00-036 | CEILING | Aa 0.15 m | 1116Dfl0000431476/03 | m² | Trockenbauarbeiten | 3 | 0.15 | 0 | 1 | Bekleidung | Aa | 0 | 0 | NEW | 2.5 | Pset_CoveringCommon - FireRating: -; AcousticRating: -; AllplanAttributes - ash_lichte Raumhöhe: 2.500000; OKFF: 0
Gipsfaserplatten 2-lagig (BSK) | WUN-H2-E00-036 | CEILING | D1 0.001 m | 1116Dfl0000431476/04 | m² | Maler- und Lackierarbeiten | 4 | 0.001 | 0 | 1 | Bekleidung | D1 | 0 | 0 | NEW | 2.5 | AllplanAttributes - ash_lichte Raumhöhe: 2.500000; OKFF: 0
PVC Bahnenware Holzoptik | WUN-H2-E00-035 | FLOORING | Ku1 0.2 m | 1116Bfl0000066678/01 | m² | Bodenbelagsarbeiten | 1 | 0.2 | 0 | 1 | Bodenfläche | Ku1 | 0 | 0 | NEW | AllplanAttributes - Bezeichnung: PVC Bahnenware Holzoptik; Raumnr. Bauherr: 2.11_A2_02; ash B_Aufbau: B1; ash B_Rutschhemmung: R9
Gipsfaserplatten 2-lagig (BSK) | WUN-H2-E00-035 | CEILING | layer 0.036 m | 1116Dfl0000066691/01 | m² | Trockenbauarbeiten | 1 | 0.036 | 0 | 1 | Deckenfläche |  | 0 | 0 | NEW | 2.5 | AllplanAttributes - Bezeichnung: Gipsfaserplatten 2-lagig (BSK)
Gipsfaserplatten 2-lagig (BSK) | WUN-H2-E00-035 | CEILING | Installationshöhe 0.714 m | 1116Dfl0000066691/02 | m² | Trockenbauarbeiten | 2 | 0.714 | 0 | 1 | Bekleidung | Installationshöhe | 0 | 0 | NEW | 2.5 | Pset_CoveringCommon - FireRating: für korrekte FläVisu; AllplanAttributes - ash_lichte Raumhöhe: 2.500000; OKFF: 0
Gipsfaserplatten 2-lagig (BSK) | WUN-H2-E00-035 | CEILING | A1 0.15 m | 1116Dfl0000066691/03 | m² | Trockenbauarbeiten | 3 | 0.15 | 0 | 1 | Bekleidung | A1 | 0 | 0 | NEW | 2.5 | Pset_CoveringCommon - FireRating: -; AcousticRating: -; AllplanAttributes - ash_lichte Raumhöhe: 2.500000; OKFF: 0
Gipsfaserplatten 2-lagig (BSK) | WUN-H2-E00-035 | CEILING | D1 0.001 m | 1116Dfl0000066691/04 | m² | Maler- und Lackierarbeiten | 4 | 0.001 | 0 | 1 | Bekleidung | D1 | 0 | 0 | NEW | 2.5 | AllplanAttributes - ash_lichte Raumhöhe: 2.500000; OKFF: 0
Gipsfaserplatten 2-lagig (BSK) | WUN-H2-E00-035 | CEILING | layer 0.036 m | 1116Dfl0000432056/01 | m² | Trockenbauarbeiten | 1 | 0.036 | 0 | 1 | Deckenfläche |  | 0 | 0 | NEW | 2.5 | AllplanAttributes - Bezeichnung: Gipsfaserplatten 2-lagig (BSK)
Gipsfaserplatten 2-lagig (BSK) | WUN-H2-E00-035 | CEILING | Installationshöhe 0.714 m | 1116Dfl0000432056/02 | m² | Trockenbauarbeiten | 2 | 0.714 | 0 | 1 | Bekleidung | Installationshöhe | 0 | 0 | NEW | 2.5 | Pset_CoveringCommon - FireRating: für korrekte FläVisu; AllplanAttributes - ash_lichte Raumhöhe: 2.500000; OKFF: 0
Gipsfaserplatten 2-lagig (BSK) | WUN-H2-E00-035 | CEILING | Aa 0.15 m | 1116Dfl0000432056/03 | m² | Trockenbauarbeiten | 3 | 0.15 | 0 | 1 | Bekleidung | Aa | 0 | 0 | NEW | 2.5 | Pset_CoveringCommon - FireRating: -; AcousticRating: -; AllplanAttributes - ash_lichte Raumhöhe: 2.500000; OKFF: 0
Gipsfaserplatten 2-lagig (BSK) | WUN-H2-E00-035 | CEILING | D1 0.001 m | 1116Dfl0000432056/04 | m² | Maler- und Lackierarbeiten | 4 | 0.001 | 0 | 1 | Bekleidung | D1 | 0 | 0 | NEW | 2.5 | AllplanAttributes - ash_lichte Raumhöhe: 2.500000; OKFF: 0
PVC Bahnenware Holzoptik | WUN-H2-E00-034 | FLOORING | Ku1 0.2 m | 1116Bfl0000066647/01 | m² | Bodenbelagsarbeiten | 1 | 0.2 | 0 | 1 | Bodenfläche | Ku1 | 0 | 0 | NEW | AllplanAttributes - Bezeichnung: PVC Bahnenware Holzoptik; Raumnr. Bauherr: 2.11_A2_02; ash B_Aufbau: B1; ash B_Rutschhemmung: R9
Gipsfaserplatten 2-lagig (BSK) | WUN-H2-E00-034 | CEILING | layer 0.036 m | 1116Dfl0000066663/01 | m² | Trockenbauarbeiten | 1 | 0.036 | 0 | 1 | Deckenfläche |  | 0 | 0 | NEW | 2.5 | AllplanAttributes - Bezeichnung: Gipsfaserplatten 2-lagig (BSK)
Gipsfaserplatten 2-lagig (BSK) | WUN-H2-E00-034 | CEILING | Installationshöhe 0.714 m | 1116Dfl0000066663/02 | m² | Trockenbauarbeiten | 2 | 0.714 | 0 | 1 | Bekleidung | Installationshöhe | 0 | 0 | NEW | 2.5 | Pset_CoveringCommon - FireRating: für korrekte FläVisu; AllplanAttributes - ash_lichte Raumhöhe: 2.500000; OKFF: 0
Gipsfaserplatten 2-lagig (BSK) | WUN-H2-E00-034 | CEILING | A1 0.15 m | 1116Dfl0000066663/03 | m² | Trockenbauarbeiten | 3 | 0.15 | 0 | 1 | Bekleidung | A1 | 0 | 0 | NEW | 2.5 | Pset_CoveringCommon - FireRating: -; AcousticRating: -; AllplanAttributes - ash_lichte Raumhöhe: 2.500000; OKFF: 0
Gipsfaserplatten 2-lagig (BSK) | WUN-H2-E00-034 | CEILING | D1 0.001 m | 1116Dfl0000066663/04 | m² | Maler- und Lackierarbeiten | 4 | 0.001 | 0 | 1 | Bekleidung | D1 | 0 | 0 | NEW | 2.5 | AllplanAttributes - ash_lichte Raumhöhe: 2.500000; OKFF: 0
Gipsfaserplatten 2-lagig (BSK) | WUN-H2-E00-034 | CEILING | layer 0.036 m | 1116Dfl0000432636/01 | m² | Trockenbauarbeiten | 1 | 0.036 | 0 | 1 | Deckenfläche |  | 0 | 0 | NEW | 2.5 | AllplanAttributes - Bezeichnung: Gipsfaserplatten 2-lagig (BSK)
Gipsfaserplatten 2-lagig (BSK) | WUN-H2-E00-034 | CEILING | Installationshöhe 0.714 m | 1116Dfl0000432636/02 | m² | Trockenbauarbeiten | 2 | 0.714 | 0 | 1 | Bekleidung | Installationshöhe | 0 | 0 | NEW | 2.5 | Pset_CoveringCommon - FireRating: für korrekte FläVisu; AllplanAttributes - ash_lichte Raumhöhe: 2.500000; OKFF: 0
Gipsfaserplatten 2-lagig (BSK) | WUN-H2-E00-034 | CEILING | Aa 0.15 m | 1116Dfl0000432636/03 | m² | Trockenbauarbeiten | 3 | 0.15 | 0 | 1 | Bekleidung | Aa | 0 | 0 | NEW | 2.5 | Pset_CoveringCommon - FireRating: -; AcousticRating: -; AllplanAttributes - ash_lichte Raumhöhe: 2.500000; OKFF: 0
Gipsfaserplatten 2-lagig (BSK) | WUN-H2-E00-034 | CEILING | D1 0.001 m | 1116Dfl0000432636/04 | m² | Maler- und Lackierarbeiten | 4 | 0.001 | 0 | 1 | Bekleidung | D1 | 0 | 0 | NEW | 2.5 | AllplanAttributes - ash_lichte Raumhöhe: 2.500000; OKFF: 0
 | WUN-H2-E00-033 | SKIRTINGBOARD |  | 1116Lei0000232051 | m |  |  |  |  | 1 | Leiste |  | 0 | 0 | NEW
PVC Bahnenware Holzoptik | WUN-H2-E00-033 | FLOORING | Ku1 0.2 m | 1116Bfl0000066645/01 | m² | Bodenbelagsarbeiten | 1 | 0.2 | 0 | 1 | Bodenfläche | Ku1 | 0 | 0 | NEW | AllplanAttributes - Bezeichnung: PVC Bahnenware Holzoptik; Raumnr. Bauherr: 2.11_A2_02; ash B_Aufbau: B1; ash B_Rutschhemmung: R9
Gipsfaserplatten 2-lagig (BSK) | WUN-H2-E00-033 | CEILING | layer 0.036 m | 1116Dfl0000066661/01 | m² | Trockenbauarbeiten | 1 | 0.036 | 0 | 1 | Deckenfläche |  | 0 | 0 | NEW | 2.5 | AllplanAttributes - Bezeichnung: Gipsfaserplatten 2-lagig (BSK)
Gipsfaserplatten 2-lagig (BSK) | WUN-H2-E00-033 | CEILING | Installationshöhe 0.714 m | 1116Dfl0000066661/02 | m² | Trockenbauarbeiten | 2 | 0.714 | 0 | 1 | Bekleidung | Installationshöhe | 0 | 0 | NEW | 2.5 | Pset_CoveringCommon - FireRating: für korrekte FläVisu; AllplanAttributes - ash_lichte Raumhöhe: 2.500000; OKFF: 0
Gipsfaserplatten 2-lagig (BSK) | WUN-H2-E00-033 | CEILING | A1 0.15 m | 1116Dfl0000066661/03 | m² | Trockenbauarbeiten | 3 | 0.15 | 0 | 1 | Bekleidung | A1 | 0 | 0 | NEW | 2.5 | Pset_CoveringCommon - FireRating: -; AcousticRating: -; AllplanAttributes - ash_lichte Raumhöhe: 2.500000; OKFF: 0
Gipsfaserplatten 2-lagig (BSK) | WUN-H2-E00-033 | CEILING | D1 0.001 m | 1116Dfl0000066661/04 | m² | Maler- und Lackierarbeiten | 4 | 0.001 | 0 | 1 | Bekleidung | D1 | 0 | 0 | NEW | 2.5 | AllplanAttributes - ash_lichte Raumhöhe: 2.500000; OKFF: 0
Gipsfaserplatten 2-lagig (BSK) | WUN-H2-E00-033 | CEILING | layer 0.036 m | 1116Dfl0000433216/01 | m² | Trockenbauarbeiten | 1 | 0.036 | 0 | 1 | Deckenfläche |  | 0 | 0 | NEW | 2.5 | AllplanAttributes - Bezeichnung: Gipsfaserplatten 2-lagig (BSK)
Gipsfaserplatten 2-lagig (BSK) | WUN-H2-E00-033 | CEILING | Installationshöhe 0.714 m | 1116Dfl0000433216/02 | m² | Trockenbauarbeiten | 2 | 0.714 | 0 | 1 | Bekleidung | Installationshöhe | 0 | 0 | NEW | 2.5 | Pset_CoveringCommon - FireRating: für korrekte FläVisu; AllplanAttributes - ash_lichte Raumhöhe: 2.500000; OKFF: 0
Gipsfaserplatten 2-lagig (BSK) | WUN-H2-E00-033 | CEILING | Aa 0.15 m | 1116Dfl0000433216/03 | m² | Trockenbauarbeiten | 3 | 0.15 | 0 | 1 | Bekleidung | Aa | 0 | 0 | NEW | 2.5 | Pset_CoveringCommon - FireRating: -; AcousticRating: -; AllplanAttributes - ash_lichte Raumhöhe: 2.500000; OKFF: 0
Gipsfaserplatten 2-lagig (BSK) | WUN-H2-E00-033 | CEILING | D1 0.001 m | 1116Dfl0000433216/04 | m² | Maler- und Lackierarbeiten | 4 | 0.001 | 0 | 1 | Bekleidung | D1 | 0 | 0 | NEW | 2.5 | AllplanAttributes - ash_lichte Raumhöhe: 2.500000; OKFF: 0
 | WUN-H2-E00-007 | SKIRTINGBOARD |  | 1116Lei0000232081 | m |  |  |  |  | 1 | Leiste |  | 0 | 0 | NEW
PVC Bahnenware Holzoptik | WUN-H2-E00-007 | FLOORING | Ku1 0.2 m | 1116Bfl0000065559/01 | m² | Bodenbelagsarbeiten | 1 | 0.2 | 0 | 1 | Bodenfläche | Ku1 | 0 | 0 | NEW | AllplanAttributes - Bezeichnung: PVC Bahnenware Holzoptik; Raumnr. Bauherr: 2.11_A2_02; ash B_Aufbau: B1; ash B_Rutschhemmung: R9
Gipsfaserplatten 2-lagig (BSK) | WUN-H2-E00-007 | CEILING | layer 0.036 m | 1116Dfl0000435568/01 | m² | Trockenbauarbeiten | 1 | 0.036 | 0 | 1 | Deckenfläche |  | 0 | 0 | NEW | 2.5 | AllplanAttributes - Bezeichnung: Gipsfaserplatten 2-lagig (BSK)
Gipsfaserplatten 2-lagig (BSK) | WUN-H2-E00-007 | CEILING | Installationshöhe 0.714 m | 1116Dfl0000435568/02 | m² | Trockenbauarbeiten | 2 | 0.714 | 0 | 1 | Bekleidung | Installationshöhe | 0 | 0 | NEW | 2.5 | Pset_CoveringCommon - FireRating: für korrekte FläVisu; AllplanAttributes - ash_lichte Raumhöhe: 2.500000; OKFF: 0
Gipsfaserplatten 2-lagig (BSK) | WUN-H2-E00-007 | CEILING | Aa 0.15 m | 1116Dfl0000435568/03 | m² | Trockenbauarbeiten | 3 | 0.15 | 0 | 1 | Bekleidung | Aa | 0 | 0 | NEW | 2.5 | Pset_CoveringCommon - FireRating: -; AcousticRating: -; AllplanAttributes - ash_lichte Raumhöhe: 2.500000; OKFF: 0
Gipsfaserplatten 2-lagig (BSK) | WUN-H2-E00-007 | CEILING | D1 0.001 m | 1116Dfl0000435568/04 | m² | Maler- und Lackierarbeiten | 4 | 0.001 | 0 | 1 | Bekleidung | D1 | 0 | 0 | NEW | 2.5 | AllplanAttributes - ash_lichte Raumhöhe: 2.500000; OKFF: 0
Gipsfaserplatten 2-lagig (BSK) | WUN-H2-E00-007 | CEILING | layer 0.036 m | 1116Dfl0000065899/01 | m² | Trockenbauarbeiten | 1 | 0.036 | 0 | 1 | Deckenfläche |  | 0 | 0 | NEW | 2.5 | AllplanAttributes - Bezeichnung: Gipsfaserplatten 2-lagig (BSK)
Gipsfaserplatten 2-lagig (BSK) | WUN-H2-E00-007 | CEILING | Installationshöhe 0.714 m | 1116Dfl0000065899/02 | m² | Trockenbauarbeiten | 2 | 0.714 | 0 | 1 | Bekleidung | Installationshöhe | 0 | 0 | NEW | 2.5 | Pset_CoveringCommon - FireRating: für korrekte FläVisu; AllplanAttributes - ash_lichte Raumhöhe: 2.500000; OKFF: 0
Gipsfaserplatten 2-lagig (BSK) | WUN-H2-E00-007 | CEILING | A1 0.15 m | 1116Dfl0000065899/03 | m² | Trockenbauarbeiten | 3 | 0.15 | 0 | 1 | Bekleidung | A1 | 0 | 0 | NEW | 2.5 | Pset_CoveringCommon - FireRating: -; AcousticRating: -; AllplanAttributes - ash_lichte Raumhöhe: 2.500000; OKFF: 0
Gipsfaserplatten 2-lagig (BSK) | WUN-H2-E00-007 | CEILING | D1 0.001 m | 1116Dfl0000065899/04 | m² | Maler- und Lackierarbeiten | 4 | 0.001 | 0 | 1 | Bekleidung | D1 | 0 | 0 | NEW | 2.5 | AllplanAttributes - ash_lichte Raumhöhe: 2.500000; OKFF: 0
PVC Bahnenware Holzoptik | WUN-H2-E00-005 | FLOORING | Ku1 0.2 m | 1116Bfl0000065555/01 | m² | Bodenbelagsarbeiten | 1 | 0.2 | 0 | 1 | Bodenfläche | Ku1 | 0 | 0 | NEW | AllplanAttributes - Bezeichnung: PVC Bahnenware Holzoptik; Raumnr. Bauherr: 2.11_A2_02; ash B_Aufbau: B1; ash B_Rutschhemmung: R9
Gipsfaserplatten 2-lagig (BSK) | WUN-H2-E00-005 | CEILING | layer 0.036 m | 1116Dfl0000065919/01 | m² | Trockenbauarbeiten | 1 | 0.036 | 0 | 1 | Deckenfläche |  | 0 | 0 | NEW | 2.5 | AllplanAttributes - Bezeichnung: Gipsfaserplatten 2-lagig (BSK)
Gipsfaserplatten 2-lagig (BSK) | WUN-H2-E00-005 | CEILING | Installationshöhe 0.714 m | 1116Dfl0000065919/02 | m² | Trockenbauarbeiten | 2 | 0.714 | 0 | 1 | Bekleidung | Installationshöhe | 0 | 0 | NEW | 2.5 | Pset_CoveringCommon - FireRating: für korrekte FläVisu; AllplanAttributes - ash_lichte Raumhöhe: 2.500000; OKFF: 0
Gipsfaserplatten 2-lagig (BSK) | WUN-H2-E00-005 | CEILING | A1 0.15 m | 1116Dfl0000065919/03 | m² | Trockenbauarbeiten | 3 | 0.15 | 0 | 1 | Bekleidung | A1 | 0 | 0 | NEW | 2.5 | Pset_CoveringCommon - FireRating: -; AcousticRating: -; AllplanAttributes - ash_lichte Raumhöhe: 2.500000; OKFF: 0
Gipsfaserplatten 2-lagig (BSK) | WUN-H2-E00-005 | CEILING | D1 0.001 m | 1116Dfl0000065919/04 | m² | Maler- und Lackierarbeiten | 4 | 0.001 | 0 | 1 | Bekleidung | D1 | 0 | 0 | NEW | 2.5 | AllplanAttributes - ash_lichte Raumhöhe: 2.500000; OKFF: 0
Gipsfaserplatten 2-lagig (BSK) | WUN-H2-E00-005 | CEILING | layer 0.036 m | 1116Dfl0000433818/01 | m² | Trockenbauarbeiten | 1 | 0.036 | 0 | 1 | Deckenfläche |  | 0 | 0 | NEW | 2.5 | AllplanAttributes - Bezeichnung: Gipsfaserplatten 2-lagig (BSK)
Gipsfaserplatten 2-lagig (BSK) | WUN-H2-E00-005 | CEILING | Installationshöhe 0.714 m | 1116Dfl0000433818/02 | m² | Trockenbauarbeiten | 2 | 0.714 | 0 | 1 | Bekleidung | Installationshöhe | 0 | 0 | NEW | 2.5 | Pset_CoveringCommon - FireRating: für korrekte FläVisu; AllplanAttributes - ash_lichte Raumhöhe: 2.500000; OKFF: 0
Gipsfaserplatten 2-lagig (BSK) | WUN-H2-E00-005 | CEILING | Aa 0.15 m | 1116Dfl0000433818/03 | m² | Trockenbauarbeiten | 3 | 0.15 | 0 | 1 | Bekleidung | Aa | 0 | 0 | NEW | 2.5 | Pset_CoveringCommon - FireRating: -; AcousticRating: -; AllplanAttributes - ash_lichte Raumhöhe: 2.500000; OKFF: 0
Gipsfaserplatten 2-lagig (BSK) | WUN-H2-E00-005 | CEILING | D1 0.001 m | 1116Dfl0000433818/04 | m² | Maler- und Lackierarbeiten | 4 | 0.001 | 0 | 1 | Bekleidung | D1 | 0 | 0 | NEW | 2.5 | AllplanAttributes - ash_lichte Raumhöhe: 2.500000; OKFF: 0
PVC Bahnenware Holzoptik | WUN-H2-E00-004 | FLOORING | Ku1 0.2 m | 1116Bfl0000066411/01 | m² | Bodenbelagsarbeiten | 1 | 0.2 | 0 | 1 | Bodenfläche | Ku1 | 0 | 0 | NEW | AllplanAttributes - Bezeichnung: PVC Bahnenware Holzoptik; Raumnr. Bauherr: 2.11_A2_02; ash B_Aufbau: B1; ash B_Rutschhemmung: R9
Gipsfaserplatten 2-lagig (BSK) | WUN-H2-E00-004 | CEILING | layer 0.036 m | 1116Dfl0000066416/01 | m² | Trockenbauarbeiten | 1 | 0.036 | 0 | 1 | Deckenfläche |  | 0 | 0 | NEW | 2.5 | AllplanAttributes - Bezeichnung: Gipsfaserplatten 2-lagig (BSK)
Gipsfaserplatten 2-lagig (BSK) | WUN-H2-E00-004 | CEILING | Installationshöhe 0.714 m | 1116Dfl0000066416/02 | m² | Trockenbauarbeiten | 2 | 0.714 | 0 | 1 | Bekleidung | Installationshöhe | 0 | 0 | NEW | 2.5 | Pset_CoveringCommon - FireRating: für korrekte FläVisu; AllplanAttributes - ash_lichte Raumhöhe: 2.500000; OKFF: 0
Gipsfaserplatten 2-lagig (BSK) | WUN-H2-E00-004 | CEILING | A1 0.15 m | 1116Dfl0000066416/03 | m² | Trockenbauarbeiten | 3 | 0.15 | 0 | 1 | Bekleidung | A1 | 0 | 0 | NEW | 2.5 | Pset_CoveringCommon - FireRating: -; AcousticRating: -; AllplanAttributes - ash_lichte Raumhöhe: 2.500000; OKFF: 0
Gipsfaserplatten 2-lagig (BSK) | WUN-H2-E00-004 | CEILING | D1 0.001 m | 1116Dfl0000066416/04 | m² | Maler- und Lackierarbeiten | 4 | 0.001 | 0 | 1 | Bekleidung | D1 | 0 | 0 | NEW | 2.5 | AllplanAttributes - ash_lichte Raumhöhe: 2.500000; OKFF: 0
Gipsfaserplatten 2-lagig (BSK) | WUN-H2-E00-004 | CEILING | layer 0.036 m | 1116Dfl0000434406/01 | m² | Trockenbauarbeiten | 1 | 0.036 | 0 | 1 | Deckenfläche |  | 0 | 0 | NEW | 2.5 | AllplanAttributes - Bezeichnung: Gipsfaserplatten 2-lagig (BSK)
Gipsfaserplatten 2-lagig (BSK) | WUN-H2-E00-004 | CEILING | Installationshöhe 0.714 m | 1116Dfl0000434406/02 | m² | Trockenbauarbeiten | 2 | 0.714 | 0 | 1 | Bekleidung | Installationshöhe | 0 | 0 | NEW | 2.5 | Pset_CoveringCommon - FireRating: für korrekte FläVisu; AllplanAttributes - ash_lichte Raumhöhe: 2.500000; OKFF: 0
Gipsfaserplatten 2-lagig (BSK) | WUN-H2-E00-004 | CEILING | Aa 0.15 m | 1116Dfl0000434406/03 | m² | Trockenbauarbeiten | 3 | 0.15 | 0 | 1 | Bekleidung | Aa | 0 | 0 | NEW | 2.5 | Pset_CoveringCommon - FireRating: -; AcousticRating: -; AllplanAttributes - ash_lichte Raumhöhe: 2.500000; OKFF: 0
Gipsfaserplatten 2-lagig (BSK) | WUN-H2-E00-004 | CEILING | D1 0.001 m | 1116Dfl0000434406/04 | m² | Maler- und Lackierarbeiten | 4 | 0.001 | 0 | 1 | Bekleidung | D1 | 0 | 0 | NEW | 2.5 | AllplanAttributes - ash_lichte Raumhöhe: 2.500000; OKFF: 0
PVC Bahnenware Uni | WUN-H2-E00-011 | FLOORING | Ku2 0.2 m | 1116Bfl0000066284/01 | m² | Bodenbelagsarbeiten | 1 | 0.2 | 0 | 1 | Bodenfläche | Ku2 | 0 | 0 | NEW | AllplanAttributes - Bezeichnung: PVC Bahnenware Uni; Raumnr. Bauherr: 2.11_A2_02; ash B_Aufbau: B1; ash B_Rutschhemmung: R9
Gipsfaserplatten 2-lagig (BSK) | WUN-H2-E00-011 | CEILING | layer 0.036 m | 1116Dfl0000066474/01 | m² | Trockenbauarbeiten | 1 | 0.036 | 0 | 1 | Deckenfläche |  | 0 | 0 | NEW | 2.5 | AllplanAttributes - Bezeichnung: Gipsfaserplatten 2-lagig (BSK)
Gipsfaserplatten 2-lagig (BSK) | WUN-H2-E00-011 | CEILING | Installationshöhe 0.764 m | 1116Dfl0000066474/02 | m² | Trockenbauarbeiten | 2 | 0.764 | 0 | 1 | Bekleidung | Installationshöhe | 0 | 0 | NEW | 2.5 | Pset_CoveringCommon - FireRating: für korrekte FläVisu; AllplanAttributes - ash_lichte Raumhöhe: 2.500000; OKFF: 0
Kühldecke glatt | WUN-H2-E00-011 | CEILING | H7a 0.1 m | 1116Dfl0000066474/03 | m² | Trockenbauarbeiten | 3 | 0.1 | 0 | 1 | Bekleidung | H7a | 0 | 0 | NEW | 2.5 | AllplanAttributes - Bezeichnung: Kühldecke glatt; ash_lichte Raumhöhe: 2.500000; OKFF: 0; Pset_CoveringCommon - FireRating: -; AcousticRating: -
Gipsfaserplatten 2-lagig (BSK) | WUN-H2-E00-011 | CEILING | D1 0.001 m | 1116Dfl0000066474/04 | m² | Maler- und Lackierarbeiten | 4 | 0.001 | 0 | 1 | Bekleidung | D1 | 0 | 0 | NEW | 2.5 | AllplanAttributes - ash_lichte Raumhöhe: 2.500000; OKFF: 0
PVC Bahnenware Uni | WUN-H2-E00-065 | FLOORING | Ku2 0.2 m | 1116Bfl0000066785/01 | m² | Bodenbelagsarbeiten | 1 | 0.2 | 0 | 1 | Bodenfläche | Ku2 | 0 | 0 | NEW | AllplanAttributes - Bezeichnung: PVC Bahnenware Uni; Raumnr. Bauherr: 2.11_A2_02; ash B_Aufbau: B1; ash B_Rutschhemmung: R9
Gipsfaserplatten 2-lagig (BSK) | WUN-H2-E00-065 | CEILING | layer 0.036 m | 1116Dfl0000066791/01 | m² | Trockenbauarbeiten | 1 | 0.036 | 0 | 1 | Deckenfläche |  | 0 | 0 | NEW | 2.5 | AllplanAttributes - Bezeichnung: Gipsfaserplatten 2-lagig (BSK)
Gipsfaserplatten 2-lagig (BSK) | WUN-H2-E00-065 | CEILING | Installationshöhe 0.764 m | 1116Dfl0000066791/02 | m² | Trockenbauarbeiten | 2 | 0.764 | 0 | 1 | Bekleidung | Installationshöhe | 0 | 0 | NEW | 2.5 | Pset_CoveringCommon - FireRating: für korrekte FläVisu; AllplanAttributes - ash_lichte Raumhöhe: 2.500000; OKFF: 0
Kühldecke glatt | WUN-H2-E00-065 | CEILING | H7a 0.1 m | 1116Dfl0000066791/03 | m² | Trockenbauarbeiten | 3 | 0.1 | 0 | 1 | Bekleidung | H7a | 0 | 0 | NEW | 2.5 | AllplanAttributes - Bezeichnung: Kühldecke glatt; ash_lichte Raumhöhe: 2.500000; OKFF: 0; Pset_CoveringCommon - FireRating: -; AcousticRating: -
Gipsfaserplatten 2-lagig (BSK) | WUN-H2-E00-065 | CEILING | D1 0.001 m | 1116Dfl0000066791/04 | m² | Maler- und Lackierarbeiten | 4 | 0.001 | 0 | 1 | Bekleidung | D1 | 0 | 0 | NEW | 2.5 | AllplanAttributes - ash_lichte Raumhöhe: 2.500000; OKFF: 0
PVC Bahnenware Holzoptik | WUN-H2-E00-066 | FLOORING | Ku1 0.2 m | 1116Bfl0000065589/01 | m² | Bodenbelagsarbeiten | 1 | 0.2 | 0 | 1 | Bodenfläche | Ku1 | 0 | 0 | NEW | AllplanAttributes - Bezeichnung: PVC Bahnenware Holzoptik; Raumnr. Bauherr: 2.11_A2_02; ash B_Aufbau: B1; ash B_Rutschhemmung: R9
Gipsfaserplatten 2-lagig (BSK) | WUN-H2-E00-066 | CEILING | layer 0.036 m | 1116Dfl0000943112/01 | m² | Trockenbauarbeiten | 1 | 0.036 | 0 | 1 | Deckenfläche |  | 0 | 0 | NEW | 2.5 | AllplanAttributes - Bezeichnung: Gipsfaserplatten 2-lagig (BSK)
Gipsfaserplatten 2-lagig (BSK) | WUN-H2-E00-066 | CEILING | Installationshöhe 0.764 m | 1116Dfl0000943112/02 | m² | Trockenbauarbeiten | 2 | 0.764 | 0 | 1 | Bekleidung | Installationshöhe | 0 | 0 | NEW | 2.5 | Pset_CoveringCommon - FireRating: für korrekte FläVisu; AllplanAttributes - ash_lichte Raumhöhe: 2.500000; OKFF: 0
Kühldecke gelocht | WUN-H2-E00-066 | CEILING | H7b 0.1 m | 1116Dfl0000943112/03 | m² | Trockenbauarbeiten | 3 | 0.1 | 0 | 1 | Bekleidung | H7b | 0 | 0 | NEW | 2.5 | AllplanAttributes - Bezeichnung: Kühldecke gelocht; ash_lichte Raumhöhe: 2.500000; OKFF: 0; Pset_CoveringCommon - FireRating: -; AcousticRating: -
Gipsfaserplatten 2-lagig (BSK) | WUN-H2-E00-066 | CEILING | D1 0.001 m | 1116Dfl0000943112/04 | m² | Maler- und Lackierarbeiten | 4 | 0.001 | 0 | 1 | Bekleidung | D1 | 0 | 0 | NEW | 2.5 | AllplanAttributes - ash_lichte Raumhöhe: 2.500000; OKFF: 0
Gipsfaserplatten 2-lagig (BSK) | WUN-H2-E00-066 | CEILING | layer 0.036 m | 1116Dfl0000065897/01 | m² | Trockenbauarbeiten | 1 | 0.036 | 0 | 1 | Deckenfläche |  | 0 | 0 | NEW | 2.5 | AllplanAttributes - Bezeichnung: Gipsfaserplatten 2-lagig (BSK)
Gipsfaserplatten 2-lagig (BSK) | WUN-H2-E00-066 | CEILING | Installationshöhe 0.764 m | 1116Dfl0000065897/02 | m² | Trockenbauarbeiten | 2 | 0.764 | 0 | 1 | Bekleidung | Installationshöhe | 0 | 0 | NEW | 2.5 | Pset_CoveringCommon - FireRating: für korrekte FläVisu; AllplanAttributes - ash_lichte Raumhöhe: 2.500000; OKFF: 0
Kühldecke glatt | WUN-H2-E00-066 | CEILING | H7a 0.1 m | 1116Dfl0000065897/03 | m² | Trockenbauarbeiten | 3 | 0.1 | 0 | 1 | Bekleidung | H7a | 0 | 0 | NEW | 2.5 | AllplanAttributes - Bezeichnung: Kühldecke glatt; ash_lichte Raumhöhe: 2.500000; OKFF: 0; Pset_CoveringCommon - FireRating: -; AcousticRating: -
Gipsfaserplatten 2-lagig (BSK) | WUN-H2-E00-066 | CEILING | D1 0.001 m | 1116Dfl0000065897/04 | m² | Maler- und Lackierarbeiten | 4 | 0.001 | 0 | 1 | Bekleidung | D1 | 0 | 0 | NEW | 2.5 | AllplanAttributes - ash_lichte Raumhöhe: 2.500000; OKFF: 0
PVC Bahnenware Uni | WUN-H2-E00-051 | FLOORING | Ku2 0.2 m | 1116Bfl0000065660/01 | m² | Bodenbelagsarbeiten | 1 | 0.2 | 0 | 1 | Bodenfläche | Ku2 | 0 | 0 | NEW | AllplanAttributes - Bezeichnung: PVC Bahnenware Uni; Raumnr. Bauherr: 2.11_A2_02; ash B_Aufbau: B1; ash B_Rutschhemmung: R9
Gipsfaserplatten 2-lagig (BSK) | WUN-H2-E00-051 | CEILING | layer 0.036 m | 1116Dfl0000229414/01 | m² | Trockenbauarbeiten | 1 | 0.036 | 0 | 1 | Deckenfläche |  | 0 | 0 | NEW | 2.5 | AllplanAttributes - Bezeichnung: Gipsfaserplatten 2-lagig (BSK)
Gipsfaserplatten 2-lagig (BSK) | WUN-H2-E00-051 | CEILING | Installationshöhe 0.764 m | 1116Dfl0000229414/02 | m² | Trockenbauarbeiten | 2 | 0.764 | 0 | 1 | Bekleidung | Installationshöhe | 0 | 0 | NEW | 2.5 | Pset_CoveringCommon - FireRating: für korrekte FläVisu; AllplanAttributes - ash_lichte Raumhöhe: 2.500000; OKFF: 0
Gipsfaserplatten 2-lagig (BSK) | WUN-H2-E00-051 | CEILING | A1 0.1 m | 1116Dfl0000229414/03 | m² | Trockenbauarbeiten | 3 | 0.1 | 0 | 1 | Bekleidung | A1 | 0 | 0 | NEW | 2.5 | Pset_CoveringCommon - FireRating: -; AcousticRating: -; AllplanAttributes - ash_lichte Raumhöhe: 2.500000; OKFF: 0
Gipsfaserplatten 2-lagig (BSK) | WUN-H2-E00-051 | CEILING | D1 0.001 m | 1116Dfl0000229414/04 | m² | Maler- und Lackierarbeiten | 4 | 0.001 | 0 | 1 | Bekleidung | D1 | 0 | 0 | NEW | 2.5 | AllplanAttributes - ash_lichte Raumhöhe: 2.500000; OKFF: 0
PVC Bahnenware Holzoptik | WUN-H2-E00-012a | FLOORING | Ku1 0.2 m | 1116Bfl0000066457/01 | m² | Bodenbelagsarbeiten | 1 | 0.2 | 0 | 1 | Bodenfläche | Ku1 | 0 | 0 | NEW | AllplanAttributes - Bezeichnung: PVC Bahnenware Holzoptik; Raumnr. Bauherr: 2.11_A2_02; ash B_Aufbau: B1; ash B_Rutschhemmung: R9
Gipsfaserplatten 2-lagig (BSK) | WUN-H2-E00-012a | CEILING | layer 0.036 m | 1116Dfl0000066464/01 | m² | Trockenbauarbeiten | 1 | 0.036 | 0 | 1 | Deckenfläche |  | 0 | 0 | NEW | 2.5 | AllplanAttributes - Bezeichnung: Gipsfaserplatten 2-lagig (BSK)
Gipsfaserplatten 2-lagig (BSK) | WUN-H2-E00-012a | CEILING | Installationshöhe 0.764 m | 1116Dfl0000066464/02 | m² | Trockenbauarbeiten | 2 | 0.764 | 0 | 1 | Bekleidung | Installationshöhe | 0 | 0 | NEW | 2.5 | Pset_CoveringCommon - FireRating: für korrekte FläVisu; AllplanAttributes - ash_lichte Raumhöhe: 2.500000; OKFF: 0
Kühldecke glatt | WUN-H2-E00-012a | CEILING | H7a 0.1 m | 1116Dfl0000066464/03 | m² | Trockenbauarbeiten | 3 | 0.1 | 0 | 1 | Bekleidung | H7a | 0 | 0 | NEW | 2.5 | AllplanAttributes - Bezeichnung: Kühldecke glatt; ash_lichte Raumhöhe: 2.500000; OKFF: 0; Pset_CoveringCommon - FireRating: -; AcousticRating: -
Gipsfaserplatten 2-lagig (BSK) | WUN-H2-E00-012a | CEILING | D1 0.001 m | 1116Dfl0000066464/04 | m² | Maler- und Lackierarbeiten | 4 | 0.001 | 0 | 1 | Bekleidung | D1 | 0 | 0 | NEW | 2.5 | AllplanAttributes - ash_lichte Raumhöhe: 2.500000; OKFF: 0
Gipsfaserplatten 2-lagig (BSK) | WUN-H2-E00-012a | CEILING | layer 0.036 m | 1116Dfl0000941731/01 | m² | Trockenbauarbeiten | 1 | 0.036 | 0 | 1 | Deckenfläche |  | 0 | 0 | NEW | 2.5 | AllplanAttributes - Bezeichnung: Gipsfaserplatten 2-lagig (BSK)
Gipsfaserplatten 2-lagig (BSK) | WUN-H2-E00-012a | CEILING | Installationshöhe 0.764 m | 1116Dfl0000941731/02 | m² | Trockenbauarbeiten | 2 | 0.764 | 0 | 1 | Bekleidung | Installationshöhe | 0 | 0 | NEW | 2.5 | Pset_CoveringCommon - FireRating: für korrekte FläVisu; AllplanAttributes - ash_lichte Raumhöhe: 2.500000; OKFF: 0
Kühldecke gelocht | WUN-H2-E00-012a | CEILING | H7b 0.1 m | 1116Dfl0000941731/03 | m² | Trockenbauarbeiten | 3 | 0.1 | 0 | 1 | Bekleidung | H7b | 0 | 0 | NEW | 2.5 | AllplanAttributes - Bezeichnung: Kühldecke gelocht; ash_lichte Raumhöhe: 2.500000; OKFF: 0; Pset_CoveringCommon - FireRating: -; AcousticRating: -
Gipsfaserplatten 2-lagig (BSK) | WUN-H2-E00-012a | CEILING | D1 0.001 m | 1116Dfl0000941731/04 | m² | Maler- und Lackierarbeiten | 4 | 0.001 | 0 | 1 | Bekleidung | D1 | 0 | 0 | NEW | 2.5 | AllplanAttributes - ash_lichte Raumhöhe: 2.500000; OKFF: 0
PVC Bahnenware Holzoptik | WUN-H2-E00-013a | FLOORING | Ku1 0.2 m | 1116Bfl0000066436/01 | m² | Bodenbelagsarbeiten | 1 | 0.2 | 0 | 1 | Bodenfläche | Ku1 | 0 | 0 | NEW | AllplanAttributes - Bezeichnung: PVC Bahnenware Holzoptik; Raumnr. Bauherr: 2.11_A2_02; ash B_Aufbau: B1; ash B_Rutschhemmung: R9
Gipsfaserplatten 2-lagig (BSK) | WUN-H2-E00-013a | CEILING | layer 0.036 m | 1116Dfl0000066446/01 | m² | Trockenbauarbeiten | 1 | 0.036 | 0 | 1 | Deckenfläche |  | 0 | 0 | NEW | 2.75 | AllplanAttributes - Bezeichnung: Gipsfaserplatten 2-lagig (BSK)
Gipsfaserplatten 2-lagig (BSK) | WUN-H2-E00-013a | CEILING | Installationshöhe 0.464 m | 1116Dfl0000066446/02 | m² | Trockenbauarbeiten | 2 | 0.464 | 0 | 1 | Bekleidung | Installationshöhe | 0 | 0 | NEW | 2.75 | Pset_CoveringCommon - FireRating: für korrekte FläVisu; AllplanAttributes - ash_lichte Raumhöhe: 2.750000
Gipsfaserplatten 2-lagig (BSK) | WUN-H2-E00-013a | CEILING | A1 0.15 m | 1116Dfl0000066446/03 | m² | Trockenbauarbeiten | 3 | 0.15 | 0 | 1 | Bekleidung | A1 | 0 | 0 | NEW | 2.75 | AllplanAttributes - ash_lichte Raumhöhe: 2.750000; Pset_CoveringCommon - AcousticRating: -
Gipsfaserplatten 2-lagig (BSK) | WUN-H2-E00-013a | CEILING | D1 0.001 m | 1116Dfl0000066446/04 | m² | Maler- und Lackierarbeiten | 4 | 0.001 | 0 | 1 | Bekleidung | D1 | 0 | 0 | NEW | 2.75 | AllplanAttributes - ash_lichte Raumhöhe: 2.750000
Gipsfaserplatten 2-lagig (BSK) | WUN-H2-E00-013a | CEILING | layer 0.036 m | 1116Dfl0000441483/01 | m² | Trockenbauarbeiten | 1 | 0.036 | 0 | 1 | Deckenfläche |  | 0 | 0 | NEW | 2.75 | AllplanAttributes - Bezeichnung: Gipsfaserplatten 2-lagig (BSK)
Gipsfaserplatten 2-lagig (BSK) | WUN-H2-E00-013a | CEILING | Installationshöhe 0.464 m | 1116Dfl0000441483/02 | m² | Trockenbauarbeiten | 2 | 0.464 | 0 | 1 | Bekleidung | Installationshöhe | 0 | 0 | NEW | 2.75 | Pset_CoveringCommon - FireRating: für korrekte FläVisu; AllplanAttributes - ash_lichte Raumhöhe: 2.750000
Gipsfaserplatten 2-lagig (BSK) | WUN-H2-E00-013a | CEILING | Aa 0.15 m | 1116Dfl0000441483/03 | m² | Trockenbauarbeiten | 3 | 0.15 | 0 | 1 | Bekleidung | Aa | 0 | 0 | NEW | 2.75 | AllplanAttributes - ash_lichte Raumhöhe: 2.750000; Pset_CoveringCommon - AcousticRating: -
Gipsfaserplatten 2-lagig (BSK) | WUN-H2-E00-013a | CEILING | D1 0.001 m | 1116Dfl0000441483/04 | m² | Maler- und Lackierarbeiten | 4 | 0.001 | 0 | 1 | Bekleidung | D1 | 0 | 0 | NEW | 2.75 | AllplanAttributes - ash_lichte Raumhöhe: 2.750000
Gipsfaserplatten 2-lagig (BSK) | WUN-H2-E00-013a | CEILING | layer 0.036 m | 1116Dfl0000442063/01 | m² | Trockenbauarbeiten | 1 | 0.036 | 0 | 1 | Deckenfläche |  | 0 | 0 | NEW | 2.75 | AllplanAttributes - Bezeichnung: Gipsfaserplatten 2-lagig (BSK)
Gipsfaserplatten 2-lagig (BSK) | WUN-H2-E00-013a | CEILING | Installationshöhe 0.464 m | 1116Dfl0000442063/02 | m² | Trockenbauarbeiten | 2 | 0.464 | 0 | 1 | Bekleidung | Installationshöhe | 0 | 0 | NEW | 2.75 | Pset_CoveringCommon - FireRating: für korrekte FläVisu; AllplanAttributes - ash_lichte Raumhöhe: 2.750000
Gipsfaserplatten 2-lagig (BSK) | WUN-H2-E00-013a | CEILING | Aa 0.15 m | 1116Dfl0000442063/03 | m² | Trockenbauarbeiten | 3 | 0.15 | 0 | 1 | Bekleidung | Aa | 0 | 0 | NEW | 2.75 | AllplanAttributes - ash_lichte Raumhöhe: 2.750000; Pset_CoveringCommon - AcousticRating: -
Gipsfaserplatten 2-lagig (BSK) | WUN-H2-E00-013a | CEILING | D1 0.001 m | 1116Dfl0000442063/04 | m² | Maler- und Lackierarbeiten | 4 | 0.001 | 0 | 1 | Bekleidung | D1 | 0 | 0 | NEW | 2.75 | AllplanAttributes - ash_lichte Raumhöhe: 2.750000
PVC Bahnenware Holzoptik | WUN-H2-E00-064a | FLOORING | Ku1 0.2 m | 1116Bfl0000066757/01 | m² | Bodenbelagsarbeiten | 1 | 0.2 | 0 | 1 | Bodenfläche | Ku1 | 0 | 0 | NEW | AllplanAttributes - Bezeichnung: PVC Bahnenware Holzoptik; Raumnr. Bauherr: 2.11_A2_02; ash B_Aufbau: B1; ash B_Rutschhemmung: R9
Gipsfaserplatten 2-lagig (BSK) | WUN-H2-E00-064a | CEILING | layer 0.036 m | 1116Dfl0000066773/01 | m² | Trockenbauarbeiten | 1 | 0.036 | 0 | 1 | Deckenfläche |  | 0 | 0 | NEW | 2.5 | AllplanAttributes - Bezeichnung: Gipsfaserplatten 2-lagig (BSK)
Gipsfaserplatten 2-lagig (BSK) | WUN-H2-E00-064a | CEILING | Installationshöhe 0.764 m | 1116Dfl0000066773/02 | m² | Trockenbauarbeiten | 2 | 0.764 | 0 | 1 | Bekleidung | Installationshöhe | 0 | 0 | NEW | 2.5 | Pset_CoveringCommon - FireRating: für korrekte FläVisu; AllplanAttributes - ash_lichte Raumhöhe: 2.500000; OKFF: 0
Kühldecke glatt | WUN-H2-E00-064a | CEILING | H7a 0.1 m | 1116Dfl0000066773/03 | m² | Trockenbauarbeiten | 3 | 0.1 | 0 | 1 | Bekleidung | H7a | 0 | 0 | NEW | 2.5 | AllplanAttributes - Bezeichnung: Kühldecke glatt; ash_lichte Raumhöhe: 2.500000; OKFF: 0; Pset_CoveringCommon - FireRating: -; AcousticRating: -
Gipsfaserplatten 2-lagig (BSK) | WUN-H2-E00-064a | CEILING | D1 0.001 m | 1116Dfl0000066773/04 | m² | Maler- und Lackierarbeiten | 4 | 0.001 | 0 | 1 | Bekleidung | D1 | 0 | 0 | NEW | 2.5 | AllplanAttributes - ash_lichte Raumhöhe: 2.500000; OKFF: 0
Gipsfaserplatten 2-lagig (BSK) | WUN-H2-E00-064a | CEILING | layer 0.036 m | 1116Dfl0000942198/01 | m² | Trockenbauarbeiten | 1 | 0.036 | 0 | 1 | Deckenfläche |  | 0 | 0 | NEW | 2.5 | AllplanAttributes - Bezeichnung: Gipsfaserplatten 2-lagig (BSK)
Gipsfaserplatten 2-lagig (BSK) | WUN-H2-E00-064a | CEILING | Installationshöhe 0.764 m | 1116Dfl0000942198/02 | m² | Trockenbauarbeiten | 2 | 0.764 | 0 | 1 | Bekleidung | Installationshöhe | 0 | 0 | NEW | 2.5 | Pset_CoveringCommon - FireRating: für korrekte FläVisu; AllplanAttributes - ash_lichte Raumhöhe: 2.500000; OKFF: 0
Kühldecke gelocht | WUN-H2-E00-064a | CEILING | H7b 0.1 m | 1116Dfl0000942198/03 | m² | Trockenbauarbeiten | 3 | 0.1 | 0 | 1 | Bekleidung | H7b | 0 | 0 | NEW | 2.5 | AllplanAttributes - Bezeichnung: Kühldecke gelocht; ash_lichte Raumhöhe: 2.500000; OKFF: 0; Pset_CoveringCommon - FireRating: -; AcousticRating: -
Gipsfaserplatten 2-lagig (BSK) | WUN-H2-E00-064a | CEILING | D1 0.001 m | 1116Dfl0000942198/04 | m² | Maler- und Lackierarbeiten | 4 | 0.001 | 0 | 1 | Bekleidung | D1 | 0 | 0 | NEW | 2.5 | AllplanAttributes - ash_lichte Raumhöhe: 2.500000; OKFF: 0
PVC Bahnenware Holzoptik | WUN-H2-E00-058 | FLOORING | Ku1 0.2 m | 1116Bfl0000065566/01 | m² | Bodenbelagsarbeiten | 1 | 0.2 | 0 | 1 | Bodenfläche | Ku1 | 0 | 0 | NEW | AllplanAttributes - Bezeichnung: PVC Bahnenware Holzoptik; Raumnr. Bauherr: 2.11_A2_02; ash B_Aufbau: B1; ash B_Rutschhemmung: R9
Gipsfaserplatten 2-lagig (BSK) | WUN-H2-E00-058 | CEILING | layer 0.036 m | 1116Dfl0000065915/01 | m² | Trockenbauarbeiten | 1 | 0.036 | 0 | 1 | Deckenfläche |  | 0 | 0 | NEW | 2.5 | AllplanAttributes - Bezeichnung: Gipsfaserplatten 2-lagig (BSK)
Gipsfaserplatten 2-lagig (BSK) | WUN-H2-E00-058 | CEILING | Installationshöhe 0.714 m | 1116Dfl0000065915/02 | m² | Trockenbauarbeiten | 2 | 0.714 | 0 | 1 | Bekleidung | Installationshöhe | 0 | 0 | NEW | 2.5 | Pset_CoveringCommon - FireRating: für korrekte FläVisu; AllplanAttributes - ash_lichte Raumhöhe: 2.500000; OKFF: 0
Gipsfaserplatten 2-lagig (BSK) | WUN-H2-E00-058 | CEILING | A1 0.15 m | 1116Dfl0000065915/03 | m² | Trockenbauarbeiten | 3 | 0.15 | 0 | 1 | Bekleidung | A1 | 0 | 0 | NEW | 2.5 | Pset_CoveringCommon - FireRating: -; AcousticRating: -; AllplanAttributes - ash_lichte Raumhöhe: 2.500000; OKFF: 0
Gipsfaserplatten 2-lagig (BSK) | WUN-H2-E00-058 | CEILING | D1 0.001 m | 1116Dfl0000065915/04 | m² | Maler- und Lackierarbeiten | 4 | 0.001 | 0 | 1 | Bekleidung | D1 | 0 | 0 | NEW | 2.5 | AllplanAttributes - ash_lichte Raumhöhe: 2.500000; OKFF: 0
Gipsfaserplatten 2-lagig (BSK) | WUN-H2-E00-058 | CEILING | layer 0.036 m | 1116Dfl0000445005/01 | m² | Trockenbauarbeiten | 1 | 0.036 | 0 | 1 | Deckenfläche |  | 0 | 0 | NEW | 2.5 | AllplanAttributes - Bezeichnung: Gipsfaserplatten 2-lagig (BSK)
Gipsfaserplatten 2-lagig (BSK) | WUN-H2-E00-058 | CEILING | Installationshöhe 0.714 m | 1116Dfl0000445005/02 | m² | Trockenbauarbeiten | 2 | 0.714 | 0 | 1 | Bekleidung | Installationshöhe | 0 | 0 | NEW | 2.5 | Pset_CoveringCommon - FireRating: für korrekte FläVisu; AllplanAttributes - ash_lichte Raumhöhe: 2.500000; OKFF: 0
Gipsfaserplatten 2-lagig (BSK) | WUN-H2-E00-058 | CEILING | Aa 0.15 m | 1116Dfl0000445005/03 | m² | Trockenbauarbeiten | 3 | 0.15 | 0 | 1 | Bekleidung | Aa | 0 | 0 | NEW | 2.5 | Pset_CoveringCommon - FireRating: -; AcousticRating: -; AllplanAttributes - ash_lichte Raumhöhe: 2.500000; OKFF: 0
Gipsfaserplatten 2-lagig (BSK) | WUN-H2-E00-058 | CEILING | D1 0.001 m | 1116Dfl0000445005/04 | m² | Maler- und Lackierarbeiten | 4 | 0.001 | 0 | 1 | Bekleidung | D1 | 0 | 0 | NEW | 2.5 | AllplanAttributes - ash_lichte Raumhöhe: 2.500000; OKFF: 0
PVC Bahnenware Holzoptik | WUN-H2-E00-059 | FLOORING | Ku1 0.2 m | 1116Bfl0000066825/01 | m² | Bodenbelagsarbeiten | 1 | 0.2 | 0 | 1 | Bodenfläche | Ku1 | 0 | 0 | NEW | AllplanAttributes - Bezeichnung: PVC Bahnenware Holzoptik; Raumnr. Bauherr: 2.11_A2_02; ash B_Aufbau: B1; ash B_Rutschhemmung: R9
Gipsfaserplatten 2-lagig (BSK) | WUN-H2-E00-059 | CEILING | layer 0.036 m | 1116Dfl0000444419/01 | m² | Trockenbauarbeiten | 1 | 0.036 | 0 | 1 | Deckenfläche |  | 0 | 0 | NEW | 2.5 | AllplanAttributes - Bezeichnung: Gipsfaserplatten 2-lagig (BSK)
Gipsfaserplatten 2-lagig (BSK) | WUN-H2-E00-059 | CEILING | Installationshöhe 0.714 m | 1116Dfl0000444419/02 | m² | Trockenbauarbeiten | 2 | 0.714 | 0 | 1 | Bekleidung | Installationshöhe | 0 | 0 | NEW | 2.5 | Pset_CoveringCommon - FireRating: für korrekte FläVisu; AllplanAttributes - ash_lichte Raumhöhe: 2.500000; OKFF: 0
Gipsfaserplatten 2-lagig (BSK) | WUN-H2-E00-059 | CEILING | Aa 0.15 m | 1116Dfl0000444419/03 | m² | Trockenbauarbeiten | 3 | 0.15 | 0 | 1 | Bekleidung | Aa | 0 | 0 | NEW | 2.5 | Pset_CoveringCommon - FireRating: -; AcousticRating: -; AllplanAttributes - ash_lichte Raumhöhe: 2.500000; OKFF: 0
Gipsfaserplatten 2-lagig (BSK) | WUN-H2-E00-059 | CEILING | D1 0.001 m | 1116Dfl0000444419/04 | m² | Maler- und Lackierarbeiten | 4 | 0.001 | 0 | 1 | Bekleidung | D1 | 0 | 0 | NEW | 2.5 | AllplanAttributes - ash_lichte Raumhöhe: 2.500000; OKFF: 0
Gipsfaserplatten 2-lagig (BSK) | WUN-H2-E00-059 | CEILING | layer 0.036 m | 1116Dfl0000066830/01 | m² | Trockenbauarbeiten | 1 | 0.036 | 0 | 1 | Deckenfläche |  | 0 | 0 | NEW | 2.5 | AllplanAttributes - Bezeichnung: Gipsfaserplatten 2-lagig (BSK)
Gipsfaserplatten 2-lagig (BSK) | WUN-H2-E00-059 | CEILING | Installationshöhe 0.714 m | 1116Dfl0000066830/02 | m² | Trockenbauarbeiten | 2 | 0.714 | 0 | 1 | Bekleidung | Installationshöhe | 0 | 0 | NEW | 2.5 | Pset_CoveringCommon - FireRating: für korrekte FläVisu; AllplanAttributes - ash_lichte Raumhöhe: 2.500000; OKFF: 0
Gipsfaserplatten 2-lagig (BSK) | WUN-H2-E00-059 | CEILING | A1 0.15 m | 1116Dfl0000066830/03 | m² | Trockenbauarbeiten | 3 | 0.15 | 0 | 1 | Bekleidung | A1 | 0 | 0 | NEW | 2.5 | Pset_CoveringCommon - FireRating: -; AcousticRating: -; AllplanAttributes - ash_lichte Raumhöhe: 2.500000; OKFF: 0
Gipsfaserplatten 2-lagig (BSK) | WUN-H2-E00-059 | CEILING | D1 0.001 m | 1116Dfl0000066830/04 | m² | Maler- und Lackierarbeiten | 4 | 0.001 | 0 | 1 | Bekleidung | D1 | 0 | 0 | NEW | 2.5 | AllplanAttributes - ash_lichte Raumhöhe: 2.500000; OKFF: 0
PVC Bahnenware Holzoptik | WUN-H2-E00-056 | FLOORING | Ku1 0.2 m | 1116Bfl0000066797/01 | m² | Bodenbelagsarbeiten | 1 | 0.2 | 0 | 1 | Bodenfläche | Ku1 | 0 | 0 | NEW | AllplanAttributes - Bezeichnung: PVC Bahnenware Holzoptik; Raumnr. Bauherr: 2.11_A2_02; ash B_Aufbau: B1; ash B_Rutschhemmung: R9
Gipsfaserplatten 2-lagig (BSK) | WUN-H2-E00-056 | CEILING | layer 0.036 m | 1116Dfl0000066813/01 | m² | Trockenbauarbeiten | 1 | 0.036 | 0 | 1 | Deckenfläche |  | 0 | 0 | NEW | 2.5 | AllplanAttributes - Bezeichnung: Gipsfaserplatten 2-lagig (BSK)
Gipsfaserplatten 2-lagig (BSK) | WUN-H2-E00-056 | CEILING | Installationshöhe 0.714 m | 1116Dfl0000066813/02 | m² | Trockenbauarbeiten | 2 | 0.714 | 0 | 1 | Bekleidung | Installationshöhe | 0 | 0 | NEW | 2.5 | Pset_CoveringCommon - FireRating: für korrekte FläVisu; AllplanAttributes - ash_lichte Raumhöhe: 2.500000; OKFF: 0
Gipsfaserplatten 2-lagig (BSK) | WUN-H2-E00-056 | CEILING | A1 0.15 m | 1116Dfl0000066813/03 | m² | Trockenbauarbeiten | 3 | 0.15 | 0 | 1 | Bekleidung | A1 | 0 | 0 | NEW | 2.5 | Pset_CoveringCommon - FireRating: -; AcousticRating: -; AllplanAttributes - ash_lichte Raumhöhe: 2.500000; OKFF: 0
Gipsfaserplatten 2-lagig (BSK) | WUN-H2-E00-056 | CEILING | D1 0.001 m | 1116Dfl0000066813/04 | m² | Maler- und Lackierarbeiten | 4 | 0.001 | 0 | 1 | Bekleidung | D1 | 0 | 0 | NEW | 2.5 | AllplanAttributes - ash_lichte Raumhöhe: 2.500000; OKFF: 0
Gipsfaserplatten 2-lagig (BSK) | WUN-H2-E00-056 | CEILING | layer 0.036 m | 1116Dfl0000446182/01 | m² | Trockenbauarbeiten | 1 | 0.036 | 0 | 1 | Deckenfläche |  | 0 | 0 | NEW | 2.5 | AllplanAttributes - Bezeichnung: Gipsfaserplatten 2-lagig (BSK)
Gipsfaserplatten 2-lagig (BSK) | WUN-H2-E00-056 | CEILING | Installationshöhe 0.714 m | 1116Dfl0000446182/02 | m² | Trockenbauarbeiten | 2 | 0.714 | 0 | 1 | Bekleidung | Installationshöhe | 0 | 0 | NEW | 2.5 | Pset_CoveringCommon - FireRating: für korrekte FläVisu; AllplanAttributes - ash_lichte Raumhöhe: 2.500000; OKFF: 0
Gipsfaserplatten 2-lagig (BSK) | WUN-H2-E00-056 | CEILING | Aa 0.15 m | 1116Dfl0000446182/03 | m² | Trockenbauarbeiten | 3 | 0.15 | 0 | 1 | Bekleidung | Aa | 0 | 0 | NEW | 2.5 | Pset_CoveringCommon - FireRating: -; AcousticRating: -; AllplanAttributes - ash_lichte Raumhöhe: 2.500000; OKFF: 0
Gipsfaserplatten 2-lagig (BSK) | WUN-H2-E00-056 | CEILING | D1 0.001 m | 1116Dfl0000446182/04 | m² | Maler- und Lackierarbeiten | 4 | 0.001 | 0 | 1 | Bekleidung | D1 | 0 | 0 | NEW | 2.5 | AllplanAttributes - ash_lichte Raumhöhe: 2.500000; OKFF: 0
PVC Bahnenware Holzoptik | WUN-H2-E00-086 | FLOORING | Ku1 0.2 m | 1116Bfl0000066717/01 | m² | Bodenbelagsarbeiten | 1 | 0.2 | 0 | 1 | Bodenfläche | Ku1 | 0 | 0 | NEW | AllplanAttributes - Bezeichnung: PVC Bahnenware Holzoptik; Raumnr. Bauherr: 2.11_A2_02; ash B_Aufbau: B1; ash B_Rutschhemmung: R9
Gipsfaserplatten 2-lagig (BSK) | WUN-H2-E00-086 | CEILING | layer 0.036 m | 1116Dfl0000449129/01 | m² | Trockenbauarbeiten | 1 | 0.036 | 0 | 1 | Deckenfläche |  | 0 | 0 | NEW | 2.5 | AllplanAttributes - Bezeichnung: Gipsfaserplatten 2-lagig (BSK)
Gipsfaserplatten 2-lagig (BSK) | WUN-H2-E00-086 | CEILING | Installationshöhe 0.714 m | 1116Dfl0000449129/02 | m² | Trockenbauarbeiten | 2 | 0.714 | 0 | 1 | Bekleidung | Installationshöhe | 0 | 0 | NEW | 2.5 | Pset_CoveringCommon - FireRating: für korrekte FläVisu; AllplanAttributes - ash_lichte Raumhöhe: 2.500000; OKFF: 0
Gipsfaserplatten 2-lagig (BSK) | WUN-H2-E00-086 | CEILING | Aa 0.15 m | 1116Dfl0000449129/03 | m² | Trockenbauarbeiten | 3 | 0.15 | 0 | 1 | Bekleidung | Aa | 0 | 0 | NEW | 2.5 | Pset_CoveringCommon - FireRating: -; AcousticRating: -; AllplanAttributes - ash_lichte Raumhöhe: 2.500000; OKFF: 0
Gipsfaserplatten 2-lagig (BSK) | WUN-H2-E00-086 | CEILING | D1 0.001 m | 1116Dfl0000449129/04 | m² | Maler- und Lackierarbeiten | 4 | 0.001 | 0 | 1 | Bekleidung | D1 | 0 | 0 | NEW | 2.5 | AllplanAttributes - ash_lichte Raumhöhe: 2.500000; OKFF: 0
Gipsfaserplatten 2-lagig (BSK) | WUN-H2-E00-086 | CEILING | layer 0.036 m | 1116Dfl0000066739/01 | m² | Trockenbauarbeiten | 1 | 0.036 | 0 | 1 | Deckenfläche |  | 0 | 0 | NEW | 2.5 | AllplanAttributes - Bezeichnung: Gipsfaserplatten 2-lagig (BSK)
Gipsfaserplatten 2-lagig (BSK) | WUN-H2-E00-086 | CEILING | Installationshöhe 0.714 m | 1116Dfl0000066739/02 | m² | Trockenbauarbeiten | 2 | 0.714 | 0 | 1 | Bekleidung | Installationshöhe | 0 | 0 | NEW | 2.5 | Pset_CoveringCommon - FireRating: für korrekte FläVisu; AllplanAttributes - ash_lichte Raumhöhe: 2.500000; OKFF: 0
Gipsfaserplatten 2-lagig (BSK) | WUN-H2-E00-086 | CEILING | A1 0.15 m | 1116Dfl0000066739/03 | m² | Trockenbauarbeiten | 3 | 0.15 | 0 | 1 | Bekleidung | A1 | 0 | 0 | NEW | 2.5 | Pset_CoveringCommon - FireRating: -; AcousticRating: -; AllplanAttributes - ash_lichte Raumhöhe: 2.500000; OKFF: 0
Gipsfaserplatten 2-lagig (BSK) | WUN-H2-E00-086 | CEILING | D1 0.001 m | 1116Dfl0000066739/04 | m² | Maler- und Lackierarbeiten | 4 | 0.001 | 0 | 1 | Bekleidung | D1 | 0 | 0 | NEW | 2.5 | AllplanAttributes - ash_lichte Raumhöhe: 2.500000; OKFF: 0
PVC Bahnenware Holzoptik | WUN-H2-E00-085 | FLOORING | Ku1 0.2 m | 1116Bfl0000066719/01 | m² | Bodenbelagsarbeiten | 1 | 0.2 | 0 | 1 | Bodenfläche | Ku1 | 0 | 0 | NEW | AllplanAttributes - Bezeichnung: PVC Bahnenware Holzoptik; Raumnr. Bauherr: 2.11_A2_02; ash B_Aufbau: B1; ash B_Rutschhemmung: R9
Gipsfaserplatten 2-lagig (BSK) | WUN-H2-E00-085 | CEILING | layer 0.036 m | 1116Dfl0000448549/01 | m² | Trockenbauarbeiten | 1 | 0.036 | 0 | 1 | Deckenfläche |  | 0 | 0 | NEW | 2.5 | AllplanAttributes - Bezeichnung: Gipsfaserplatten 2-lagig (BSK)
Gipsfaserplatten 2-lagig (BSK) | WUN-H2-E00-085 | CEILING | Installationshöhe 0.714 m | 1116Dfl0000448549/02 | m² | Trockenbauarbeiten | 2 | 0.714 | 0 | 1 | Bekleidung | Installationshöhe | 0 | 0 | NEW | 2.5 | Pset_CoveringCommon - FireRating: für korrekte FläVisu; AllplanAttributes - ash_lichte Raumhöhe: 2.500000; OKFF: 0
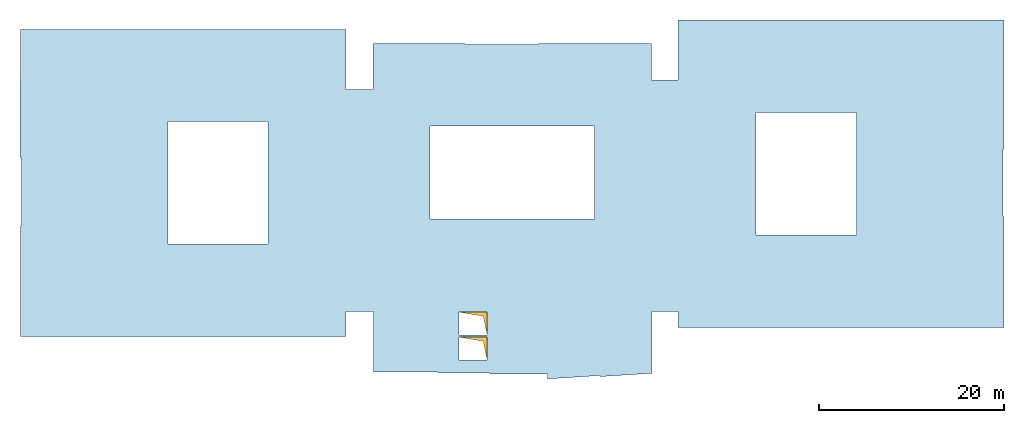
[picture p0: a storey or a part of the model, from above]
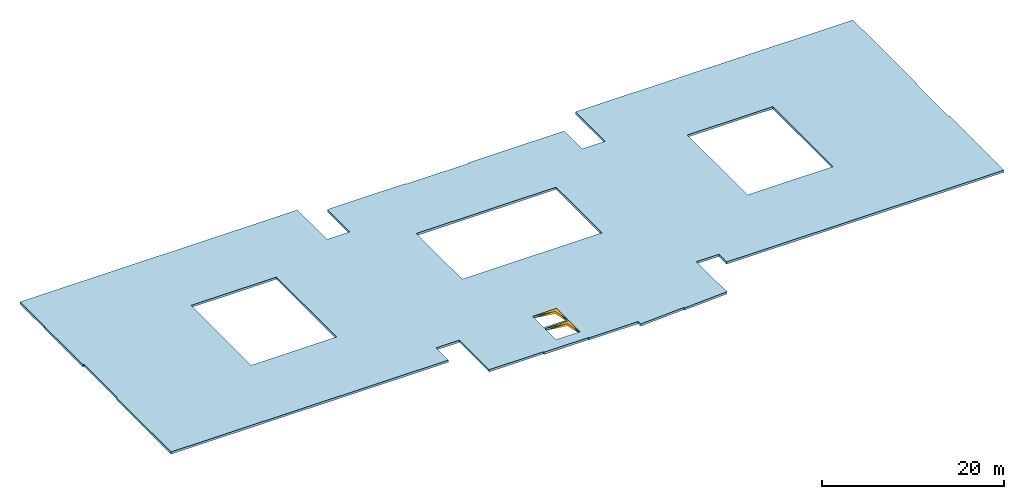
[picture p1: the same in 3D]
Properties of the parts of a building model (IFC4), part 21 of 80

# IfcCovering (3945)
Name | In | PredefinedType | Material | Allright_Bauteil_ID | Abrechnungsart | Gewerk | Schichtnummer | Schichtdicke (m) | Dicke (m) | Faktor | Objektname | AllplanAttributes, Material | Bezugshöhe | Deltahöhe | Status | D_lichte Raumhöhe [Zahl] (m)
Gipsfaserplatten 2-lagig (BSK) | WUN-H2-E00-085 | CEILING | Aa 0.15 m | 1116Dfl0000448549/03 | m² | Trockenbauarbeiten | 3 | 0.15 | 0 | 1 | Bekleidung | Aa | 0 | 0 | NEW | 2.5 | Pset_CoveringCommon - FireRating: -; AcousticRating: -; AllplanAttributes - ash_lichte Raumhöhe: 2.500000; OKFF: 0
Gipsfaserplatten 2-lagig (BSK) | WUN-H2-E00-085 | CEILING | D1 0.001 m | 1116Dfl0000448549/04 | m² | Maler- und Lackierarbeiten | 4 | 0.001 | 0 | 1 | Bekleidung | D1 | 0 | 0 | NEW | 2.5 | AllplanAttributes - ash_lichte Raumhöhe: 2.500000; OKFF: 0
Gipsfaserplatten 2-lagig (BSK) | WUN-H2-E00-085 | CEILING | layer 0.036 m | 1116Dfl0000066741/01 | m² | Trockenbauarbeiten | 1 | 0.036 | 0 | 1 | Deckenfläche |  | 0 | 0 | NEW | 2.5 | AllplanAttributes - Bezeichnung: Gipsfaserplatten 2-lagig (BSK)
Gipsfaserplatten 2-lagig (BSK) | WUN-H2-E00-085 | CEILING | Installationshöhe 0.714 m | 1116Dfl0000066741/02 | m² | Trockenbauarbeiten | 2 | 0.714 | 0 | 1 | Bekleidung | Installationshöhe | 0 | 0 | NEW | 2.5 | Pset_CoveringCommon - FireRating: für korrekte FläVisu; AllplanAttributes - ash_lichte Raumhöhe: 2.500000; OKFF: 0
Gipsfaserplatten 2-lagig (BSK) | WUN-H2-E00-085 | CEILING | A1 0.15 m | 1116Dfl0000066741/03 | m² | Trockenbauarbeiten | 3 | 0.15 | 0 | 1 | Bekleidung | A1 | 0 | 0 | NEW | 2.5 | Pset_CoveringCommon - FireRating: -; AcousticRating: -; AllplanAttributes - ash_lichte Raumhöhe: 2.500000; OKFF: 0
Gipsfaserplatten 2-lagig (BSK) | WUN-H2-E00-085 | CEILING | D1 0.001 m | 1116Dfl0000066741/04 | m² | Maler- und Lackierarbeiten | 4 | 0.001 | 0 | 1 | Bekleidung | D1 | 0 | 0 | NEW | 2.5 | AllplanAttributes - ash_lichte Raumhöhe: 2.500000; OKFF: 0
PVC Bahnenware Holzoptik | WUN-H2-E00-084 | FLOORING | Ku1 0.2 m | 1116Bfl0000066715/01 | m² | Bodenbelagsarbeiten | 1 | 0.2 | 0 | 1 | Bodenfläche | Ku1 | 0 | 0 | NEW | AllplanAttributes - Bezeichnung: PVC Bahnenware Holzoptik; Raumnr. Bauherr: 2.11_A2_02; ash B_Aufbau: B1; ash B_Rutschhemmung: R9
Gipsfaserplatten 2-lagig (BSK) | WUN-H2-E00-084 | CEILING | layer 0.036 m | 1116Dfl0000447969/01 | m² | Trockenbauarbeiten | 1 | 0.036 | 0 | 1 | Deckenfläche |  | 0 | 0 | NEW | 2.5 | AllplanAttributes - Bezeichnung: Gipsfaserplatten 2-lagig (BSK)
Gipsfaserplatten 2-lagig (BSK) | WUN-H2-E00-084 | CEILING | Installationshöhe 0.714 m | 1116Dfl0000447969/02 | m² | Trockenbauarbeiten | 2 | 0.714 | 0 | 1 | Bekleidung | Installationshöhe | 0 | 0 | NEW | 2.5 | Pset_CoveringCommon - FireRating: für korrekte FläVisu; AllplanAttributes - ash_lichte Raumhöhe: 2.500000; OKFF: 0
Gipsfaserplatten 2-lagig (BSK) | WUN-H2-E00-084 | CEILING | Aa 0.15 m | 1116Dfl0000447969/03 | m² | Trockenbauarbeiten | 3 | 0.15 | 0 | 1 | Bekleidung | Aa | 0 | 0 | NEW | 2.5 | Pset_CoveringCommon - FireRating: -; AcousticRating: -; AllplanAttributes - ash_lichte Raumhöhe: 2.500000; OKFF: 0
Gipsfaserplatten 2-lagig (BSK) | WUN-H2-E00-084 | CEILING | D1 0.001 m | 1116Dfl0000447969/04 | m² | Maler- und Lackierarbeiten | 4 | 0.001 | 0 | 1 | Bekleidung | D1 | 0 | 0 | NEW | 2.5 | AllplanAttributes - ash_lichte Raumhöhe: 2.500000; OKFF: 0
Gipsfaserplatten 2-lagig (BSK) | WUN-H2-E00-084 | CEILING | layer 0.036 m | 1116Dfl0000066743/01 | m² | Trockenbauarbeiten | 1 | 0.036 | 0 | 1 | Deckenfläche |  | 0 | 0 | NEW | 2.5 | AllplanAttributes - Bezeichnung: Gipsfaserplatten 2-lagig (BSK)
Gipsfaserplatten 2-lagig (BSK) | WUN-H2-E00-084 | CEILING | Installationshöhe 0.714 m | 1116Dfl0000066743/02 | m² | Trockenbauarbeiten | 2 | 0.714 | 0 | 1 | Bekleidung | Installationshöhe | 0 | 0 | NEW | 2.5 | Pset_CoveringCommon - FireRating: für korrekte FläVisu; AllplanAttributes - ash_lichte Raumhöhe: 2.500000; OKFF: 0
Gipsfaserplatten 2-lagig (BSK) | WUN-H2-E00-084 | CEILING | A1 0.15 m | 1116Dfl0000066743/03 | m² | Trockenbauarbeiten | 3 | 0.15 | 0 | 1 | Bekleidung | A1 | 0 | 0 | NEW | 2.5 | Pset_CoveringCommon - FireRating: -; AcousticRating: -; AllplanAttributes - ash_lichte Raumhöhe: 2.500000; OKFF: 0
Gipsfaserplatten 2-lagig (BSK) | WUN-H2-E00-084 | CEILING | D1 0.001 m | 1116Dfl0000066743/04 | m² | Maler- und Lackierarbeiten | 4 | 0.001 | 0 | 1 | Bekleidung | D1 | 0 | 0 | NEW | 2.5 | AllplanAttributes - ash_lichte Raumhöhe: 2.500000; OKFF: 0
PVC Bahnenware Holzoptik | WUN-H2-E00-083 | FLOORING | Ku1 0.2 m | 1116Bfl0000066701/01 | m² | Bodenbelagsarbeiten | 1 | 0.2 | 0 | 1 | Bodenfläche | Ku1 | 0 | 0 | NEW | AllplanAttributes - Bezeichnung: PVC Bahnenware Holzoptik; Raumnr. Bauherr: 2.11_A2_02; ash B_Aufbau: B1; ash B_Rutschhemmung: R9
Gipsfaserplatten 2-lagig (BSK) | WUN-H2-E00-083 | CEILING | layer 0.036 m | 1116Dfl0000066709/01 | m² | Trockenbauarbeiten | 1 | 0.036 | 0 | 1 | Deckenfläche |  | 0 | 0 | NEW | 2.5 | AllplanAttributes - Bezeichnung: Gipsfaserplatten 2-lagig (BSK)
Gipsfaserplatten 2-lagig (BSK) | WUN-H2-E00-083 | CEILING | Installationshöhe 0.714 m | 1116Dfl0000066709/02 | m² | Trockenbauarbeiten | 2 | 0.714 | 0 | 1 | Bekleidung | Installationshöhe | 0 | 0 | NEW | 2.5 | Pset_CoveringCommon - FireRating: für korrekte FläVisu; AllplanAttributes - ash_lichte Raumhöhe: 2.500000; OKFF: 0
Gipsfaserplatten 2-lagig (BSK) | WUN-H2-E00-083 | CEILING | A1 0.15 m | 1116Dfl0000066709/03 | m² | Trockenbauarbeiten | 3 | 0.15 | 0 | 1 | Bekleidung | A1 | 0 | 0 | NEW | 2.5 | Pset_CoveringCommon - FireRating: -; AcousticRating: -; AllplanAttributes - ash_lichte Raumhöhe: 2.500000; OKFF: 0
Gipsfaserplatten 2-lagig (BSK) | WUN-H2-E00-083 | CEILING | D1 0.001 m | 1116Dfl0000066709/04 | m² | Maler- und Lackierarbeiten | 4 | 0.001 | 0 | 1 | Bekleidung | D1 | 0 | 0 | NEW | 2.5 | AllplanAttributes - ash_lichte Raumhöhe: 2.500000; OKFF: 0
Gipsfaserplatten 2-lagig (BSK) | WUN-H2-E00-083 | CEILING | layer 0.036 m | 1116Dfl0000447389/01 | m² | Trockenbauarbeiten | 1 | 0.036 | 0 | 1 | Deckenfläche |  | 0 | 0 | NEW | 2.5 | AllplanAttributes - Bezeichnung: Gipsfaserplatten 2-lagig (BSK)
Gipsfaserplatten 2-lagig (BSK) | WUN-H2-E00-083 | CEILING | Installationshöhe 0.714 m | 1116Dfl0000447389/02 | m² | Trockenbauarbeiten | 2 | 0.714 | 0 | 1 | Bekleidung | Installationshöhe | 0 | 0 | NEW | 2.5 | Pset_CoveringCommon - FireRating: für korrekte FläVisu; AllplanAttributes - ash_lichte Raumhöhe: 2.500000; OKFF: 0
Gipsfaserplatten 2-lagig (BSK) | WUN-H2-E00-083 | CEILING | Aa 0.15 m | 1116Dfl0000447389/03 | m² | Trockenbauarbeiten | 3 | 0.15 | 0 | 1 | Bekleidung | Aa | 0 | 0 | NEW | 2.5 | Pset_CoveringCommon - FireRating: -; AcousticRating: -; AllplanAttributes - ash_lichte Raumhöhe: 2.500000; OKFF: 0
Gipsfaserplatten 2-lagig (BSK) | WUN-H2-E00-083 | CEILING | D1 0.001 m | 1116Dfl0000447389/04 | m² | Maler- und Lackierarbeiten | 4 | 0.001 | 0 | 1 | Bekleidung | D1 | 0 | 0 | NEW | 2.5 | AllplanAttributes - ash_lichte Raumhöhe: 2.500000; OKFF: 0
PVC Bahnenware Holzoptik | WUN-H2-E00-082 | FLOORING | Ku1 0.2 m | 1116Bfl0000065326/01 | m² | Bodenbelagsarbeiten | 1 | 0.2 | 0 | 1 | Bodenfläche | Ku1 | 0 | 0 | NEW | AllplanAttributes - Bezeichnung: PVC Bahnenware Holzoptik; Raumnr. Bauherr: 2.11_A2_02; ash B_Aufbau: B1; ash B_Rutschhemmung: R9
Gipsfaserplatten 2-lagig (BSK) | WUN-H2-E00-082 | CEILING | layer 0.036 m | 1116Dfl0000446809/01 | m² | Trockenbauarbeiten | 1 | 0.036 | 0 | 1 | Deckenfläche |  | 0 | 0 | NEW | 2.5 | AllplanAttributes - Bezeichnung: Gipsfaserplatten 2-lagig (BSK)
Gipsfaserplatten 2-lagig (BSK) | WUN-H2-E00-082 | CEILING | Installationshöhe 0.714 m | 1116Dfl0000446809/02 | m² | Trockenbauarbeiten | 2 | 0.714 | 0 | 1 | Bekleidung | Installationshöhe | 0 | 0 | NEW | 2.5 | Pset_CoveringCommon - FireRating: für korrekte FläVisu; AllplanAttributes - ash_lichte Raumhöhe: 2.500000; OKFF: 0
Gipsfaserplatten 2-lagig (BSK) | WUN-H2-E00-082 | CEILING | Aa 0.15 m | 1116Dfl0000446809/03 | m² | Trockenbauarbeiten | 3 | 0.15 | 0 | 1 | Bekleidung | Aa | 0 | 0 | NEW | 2.5 | Pset_CoveringCommon - FireRating: -; AcousticRating: -; AllplanAttributes - ash_lichte Raumhöhe: 2.500000; OKFF: 0
Gipsfaserplatten 2-lagig (BSK) | WUN-H2-E00-082 | CEILING | D1 0.001 m | 1116Dfl0000446809/04 | m² | Maler- und Lackierarbeiten | 4 | 0.001 | 0 | 1 | Bekleidung | D1 | 0 | 0 | NEW | 2.5 | AllplanAttributes - ash_lichte Raumhöhe: 2.500000; OKFF: 0
Gipsfaserplatten 2-lagig (BSK) | WUN-H2-E00-082 | CEILING | layer 0.036 m | 1116Dfl0000065973/01 | m² | Trockenbauarbeiten | 1 | 0.036 | 0 | 1 | Deckenfläche |  | 0 | 0 | NEW | 2.5 | AllplanAttributes - Bezeichnung: Gipsfaserplatten 2-lagig (BSK)
Gipsfaserplatten 2-lagig (BSK) | WUN-H2-E00-082 | CEILING | Installationshöhe 0.714 m | 1116Dfl0000065973/02 | m² | Trockenbauarbeiten | 2 | 0.714 | 0 | 1 | Bekleidung | Installationshöhe | 0 | 0 | NEW | 2.5 | Pset_CoveringCommon - FireRating: für korrekte FläVisu; AllplanAttributes - ash_lichte Raumhöhe: 2.500000; OKFF: 0
Gipsfaserplatten 2-lagig (BSK) | WUN-H2-E00-082 | CEILING | A1 0.15 m | 1116Dfl0000065973/03 | m² | Trockenbauarbeiten | 3 | 0.15 | 0 | 1 | Bekleidung | A1 | 0 | 0 | NEW | 2.5 | Pset_CoveringCommon - FireRating: -; AcousticRating: -; AllplanAttributes - ash_lichte Raumhöhe: 2.500000; OKFF: 0
Gipsfaserplatten 2-lagig (BSK) | WUN-H2-E00-082 | CEILING | D1 0.001 m | 1116Dfl0000065973/04 | m² | Maler- und Lackierarbeiten | 4 | 0.001 | 0 | 1 | Bekleidung | D1 | 0 | 0 | NEW | 2.5 | AllplanAttributes - ash_lichte Raumhöhe: 2.500000; OKFF: 0
Acrobyn | WUN-H2-E00-090 | CLADDING | 84 0.001 m | 1116Sfl0000430207/02 | m² | Maler- und Lackierarbeiten | 2 | 0.001 | 0 | 1 | Seitenfläche | 84 | 0 | 0 | NEW | AllplanAttributes - Bezeichnung: Acrobyn
Acrobyn | WUN-H2-E00-090 | CLADDING | 84 0.001 m | 1116Sfl0000430203/02 | m² | Maler- und Lackierarbeiten | 2 | 0.001 | 0 | 1 | Seitenfläche | 84 | 0 | 0 | NEW | AllplanAttributes - Bezeichnung: Acrobyn
PVC Bahnenware Holzoptik | WUN-H2-E00-090 | FLOORING | Ku1 0.2 m | 1116Bfl0000065308/01 | m² | Bodenbelagsarbeiten | 1 | 0.2 | 0 | 1 | Bodenfläche | Ku1 | 0 | 0 | NEW | AllplanAttributes - Bezeichnung: PVC Bahnenware Holzoptik; Raumnr. Bauherr: 2.11_A2_02; ash B_Aufbau: B1; ash B_Rutschhemmung: R9
Gipsfaserplatten 2-lagig (BSK) | WUN-H2-E00-090 | CEILING | layer 0.036 m | 1116Dfl0000065309/01 | m² | Trockenbauarbeiten | 1 | 0.036 | 0 | 1 | Deckenfläche |  | 0 | 0 | NEW | 3.15 | AllplanAttributes - Bezeichnung: Gipsfaserplatten 2-lagig (BSK)
Gipsfaserplatten 2-lagig (BSK) | WUN-H2-E00-090 | CEILING | Installationshöhe 0.114 m | 1116Dfl0000065309/02 | m² | Trockenbauarbeiten | 2 | 0.114 | 0 | 1 | Bekleidung | Installationshöhe | 0 | 0 | NEW | 3.15 | Pset_CoveringCommon - FireRating: -; AcousticRating: -; AllplanAttributes - ash_lichte Raumhöhe: 3.150000
Gipsfaserplatten 2-lagig (BSK) | WUN-H2-E00-090 | CEILING | A1 0.1 m | 1116Dfl0000065309/03 | m² | Trockenbauarbeiten | 3 | 0.1 | 0 | 1 | Bekleidung | A1 | 0 | 0 | NEW | 3.15 | Pset_CoveringCommon - FireRating: -; AcousticRating: -; AllplanAttributes - ash_lichte Raumhöhe: 3.150000
Gipsfaserplatten 2-lagig (BSK) | WUN-H2-E00-090 | CEILING | D1 0.001 m | 1116Dfl0000065309/04 | m² | Maler- und Lackierarbeiten | 4 | 0.001 | 0 | 1 | Bekleidung | D1 | 0 | 0 | NEW | 3.15 | AllplanAttributes - ash_lichte Raumhöhe: 3.150000
Gipsfaserplatten 2-lagig (BSK) | WUN-H2-E00-090 | CEILING | layer 0.036 m | 1116Dfl0000065961/01 | m² | Trockenbauarbeiten | 1 | 0.036 | 0 | 1 | Deckenfläche |  | 0 | 0 | NEW | 2.5 | AllplanAttributes - Bezeichnung: Gipsfaserplatten 2-lagig (BSK)
Gipsfaserplatten 2-lagig (BSK) | WUN-H2-E00-090 | CEILING | Installationshöhe 0.764 m | 1116Dfl0000065961/02 | m² | Trockenbauarbeiten | 2 | 0.764 | 0 | 1 | Bekleidung | Installationshöhe | 0 | 0 | NEW | 2.5 | Pset_CoveringCommon - FireRating: für korrekte FläVisu; AllplanAttributes - ash_lichte Raumhöhe: 2.500000; OKFF: 0
Gipsfaserplatten 2-lagig (BSK) | WUN-H2-E00-090 | CEILING | A1 0.1 m | 1116Dfl0000065961/03 | m² | Trockenbauarbeiten | 3 | 0.1 | 0 | 1 | Bekleidung | A1 | 0 | 0 | NEW | 2.5 | Pset_CoveringCommon - FireRating: -; AcousticRating: -; AllplanAttributes - ash_lichte Raumhöhe: 2.500000; OKFF: 0
Gipsfaserplatten 2-lagig (BSK) | WUN-H2-E00-090 | CEILING | D1 0.001 m | 1116Dfl0000065961/04 | m² | Maler- und Lackierarbeiten | 4 | 0.001 | 0 | 1 | Bekleidung | D1 | 0 | 0 | NEW | 2.5 | AllplanAttributes - ash_lichte Raumhöhe: 2.500000; OKFF: 0
Acrobyn | WUN-H2-E00-042 | CLADDING | 84 0.001 m | 1116Sfl0000430536/02 | m² | Maler- und Lackierarbeiten | 2 | 0.001 | 0 | 1 | Seitenfläche | 84 | 0 | 0 | NEW | AllplanAttributes - Bezeichnung: Acrobyn
Acrobyn | WUN-H2-E00-042 | CLADDING | 84 0.001 m | 1116Sfl0000430530/02 | m² | Maler- und Lackierarbeiten | 2 | 0.001 | 0 | 1 | Seitenfläche | 84 | 0 | 0 | NEW | AllplanAttributes - Bezeichnung: Acrobyn
PVC Bahnenware Holzoptik | WUN-H2-E00-042 | FLOORING | Ku1 0.2 m | 1116Bfl0000065290/01 | m² | Bodenbelagsarbeiten | 1 | 0.2 | 0 | 1 | Bodenfläche | Ku1 | 0 | 0 | NEW | AllplanAttributes - Bezeichnung: PVC Bahnenware Holzoptik; Raumnr. Bauherr: 2.11_A2_02; ash B_Aufbau: B1; ash B_Rutschhemmung: R9
Gipsfaserplatten 2-lagig (BSK) | WUN-H2-E00-042 | CEILING | layer 0.036 m | 1116Dfl0000065927/01 | m² | Trockenbauarbeiten | 1 | 0.036 | 0 | 1 | Deckenfläche |  | 0 | 0 | NEW | 2.5 | AllplanAttributes - Bezeichnung: Gipsfaserplatten 2-lagig (BSK)
Gipsfaserplatten 2-lagig (BSK) | WUN-H2-E00-042 | CEILING | Installationshöhe 0.764 m | 1116Dfl0000065927/02 | m² | Trockenbauarbeiten | 2 | 0.764 | 0 | 1 | Bekleidung | Installationshöhe | 0 | 0 | NEW | 2.5 | Pset_CoveringCommon - FireRating: für korrekte FläVisu; AllplanAttributes - ash_lichte Raumhöhe: 2.500000; OKFF: 0
Gipsfaserplatten 2-lagig (BSK) | WUN-H2-E00-042 | CEILING | A1 0.1 m | 1116Dfl0000065927/03 | m² | Trockenbauarbeiten | 3 | 0.1 | 0 | 1 | Bekleidung | A1 | 0 | 0 | NEW | 2.5 | Pset_CoveringCommon - FireRating: -; AcousticRating: -; AllplanAttributes - ash_lichte Raumhöhe: 2.500000; OKFF: 0
Gipsfaserplatten 2-lagig (BSK) | WUN-H2-E00-042 | CEILING | D1 0.001 m | 1116Dfl0000065927/04 | m² | Maler- und Lackierarbeiten | 4 | 0.001 | 0 | 1 | Bekleidung | D1 | 0 | 0 | NEW | 2.5 | AllplanAttributes - ash_lichte Raumhöhe: 2.500000; OKFF: 0
Gipsfaserplatten 2-lagig (BSK) | WUN-H2-E00-042 | CEILING | layer 0.036 m | 1116Dfl0000065291/01 | m² | Trockenbauarbeiten | 1 | 0.036 | 0 | 1 | Deckenfläche |  | 0 | 0 | NEW | 3.15 | AllplanAttributes - Bezeichnung: Gipsfaserplatten 2-lagig (BSK)
Gipsfaserplatten 2-lagig (BSK) | WUN-H2-E00-042 | CEILING | Installationshöhe 0.114 m | 1116Dfl0000065291/02 | m² | Trockenbauarbeiten | 2 | 0.114 | 0 | 1 | Bekleidung | Installationshöhe | 0 | 0 | NEW | 3.15 | Pset_CoveringCommon - FireRating: -; AcousticRating: -; AllplanAttributes - ash_lichte Raumhöhe: 3.150000
Gipsfaserplatten 2-lagig (BSK) | WUN-H2-E00-042 | CEILING | A1 0.1 m | 1116Dfl0000065291/03 | m² | Trockenbauarbeiten | 3 | 0.1 | 0 | 1 | Bekleidung | A1 | 0 | 0 | NEW | 3.15 | Pset_CoveringCommon - FireRating: -; AcousticRating: -; AllplanAttributes - ash_lichte Raumhöhe: 3.150000
Gipsfaserplatten 2-lagig (BSK) | WUN-H2-E00-042 | CEILING | D1 0.001 m | 1116Dfl0000065291/04 | m² | Maler- und Lackierarbeiten | 4 | 0.001 | 0 | 1 | Bekleidung | D1 | 0 | 0 | NEW | 3.15 | AllplanAttributes - ash_lichte Raumhöhe: 3.150000
Acrobyn | WUN-H2-E00-096 | CLADDING | 84 0.001 m | 1116Sfl0000430185/02 | m² | Maler- und Lackierarbeiten | 2 | 0.001 | 0 | 1 | Seitenfläche | 84 | 0 | 0 | NEW | AllplanAttributes - Bezeichnung: Acrobyn
Acrobyn | WUN-H2-E00-096 | CLADDING | 84 0.001 m | 1116Sfl0000429887/02 | m² | Maler- und Lackierarbeiten | 2 | 0.001 | 0 | 1 | Seitenfläche | 84 | 0 | 0 | NEW | AllplanAttributes - Bezeichnung: Acrobyn
PVC Bahnenware Holzoptik | WUN-H2-E00-096 | FLOORING | Ku1 0.2 m | 1116Bfl0000066492/01 | m² | Bodenbelagsarbeiten | 1 | 0.2 | 0 | 1 | Bodenfläche | Ku1 | 0 | 0 | NEW | AllplanAttributes - Bezeichnung: PVC Bahnenware Holzoptik; Raumnr. Bauherr: 2.11_A2_02; ash B_Aufbau: B1; ash B_Rutschhemmung: R9
Gipsfaserplatten 2-lagig (BSK) | WUN-H2-E00-096 | CEILING | layer 0.036 m | 1116Dfl0000066500/01 | m² | Trockenbauarbeiten | 1 | 0.036 | 0 | 1 | Deckenfläche |  | 0 | 0 | NEW | 2.5 | AllplanAttributes - Bezeichnung: Gipsfaserplatten 2-lagig (BSK)
Gipsfaserplatten 2-lagig (BSK) | WUN-H2-E00-096 | CEILING | Installationshöhe 0.764 m | 1116Dfl0000066500/02 | m² | Trockenbauarbeiten | 2 | 0.764 | 0 | 1 | Bekleidung | Installationshöhe | 0 | 0 | NEW | 2.5 | Pset_CoveringCommon - FireRating: für korrekte FläVisu; AllplanAttributes - ash_lichte Raumhöhe: 2.500000; OKFF: 0
Gipsfaserplatten 2-lagig (BSK) | WUN-H2-E00-096 | CEILING | A1 0.1 m | 1116Dfl0000066500/03 | m² | Trockenbauarbeiten | 3 | 0.1 | 0 | 1 | Bekleidung | A1 | 0 | 0 | NEW | 2.5 | Pset_CoveringCommon - FireRating: -; AcousticRating: -; AllplanAttributes - ash_lichte Raumhöhe: 2.500000; OKFF: 0
Gipsfaserplatten 2-lagig (BSK) | WUN-H2-E00-096 | CEILING | D1 0.001 m | 1116Dfl0000066500/04 | m² | Maler- und Lackierarbeiten | 4 | 0.001 | 0 | 1 | Bekleidung | D1 | 0 | 0 | NEW | 2.5 | AllplanAttributes - ash_lichte Raumhöhe: 2.500000; OKFF: 0
Gipsfaserplatten 2-lagig (BSK) | WUN-H2-E00-096 | CEILING | layer 0.036 m | 1116Dfl0000066493/01 | m² | Trockenbauarbeiten | 1 | 0.036 | 0 | 1 | Deckenfläche |  | 0 | 0 | NEW | 3.15 | AllplanAttributes - Bezeichnung: Gipsfaserplatten 2-lagig (BSK)
Gipsfaserplatten 2-lagig (BSK) | WUN-H2-E00-096 | CEILING | Installationshöhe 0.114 m | 1116Dfl0000066493/02 | m² | Trockenbauarbeiten | 2 | 0.114 | 0 | 1 | Bekleidung | Installationshöhe | 0 | 0 | NEW | 3.15 | Pset_CoveringCommon - FireRating: -; AcousticRating: -; AllplanAttributes - ash_lichte Raumhöhe: 3.150000
Gipsfaserplatten 2-lagig (BSK) | WUN-H2-E00-096 | CEILING | A1 0.1 m | 1116Dfl0000066493/03 | m² | Trockenbauarbeiten | 3 | 0.1 | 0 | 1 | Bekleidung | A1 | 0 | 0 | NEW | 3.15 | Pset_CoveringCommon - FireRating: -; AcousticRating: -; AllplanAttributes - ash_lichte Raumhöhe: 3.150000
Gipsfaserplatten 2-lagig (BSK) | WUN-H2-E00-096 | CEILING | D1 0.001 m | 1116Dfl0000066493/04 | m² | Maler- und Lackierarbeiten | 4 | 0.001 | 0 | 1 | Bekleidung | D1 | 0 | 0 | NEW | 3.15 | AllplanAttributes - ash_lichte Raumhöhe: 3.150000
Acrobyn | WUN-H2-E00-074 | CLADDING | 84 0.001 m | 1116Sfl0000430843/02 | m² | Maler- und Lackierarbeiten | 2 | 0.001 | 0 | 1 | Seitenfläche | 84 | 0 | 0 | NEW | AllplanAttributes - Bezeichnung: Acrobyn
Acrobyn | WUN-H2-E00-074 | CLADDING | 84 0.001 m | 1116Sfl0000430849/02 | m² | Maler- und Lackierarbeiten | 2 | 0.001 | 0 | 1 | Seitenfläche | 84 | 0 | 0 | NEW | AllplanAttributes - Bezeichnung: Acrobyn
PVC Bahnenware Holzoptik | WUN-H2-E00-074 | FLOORING | Ku1 0.2 m | 1116Bfl0000065270/01 | m² | Bodenbelagsarbeiten | 1 | 0.2 | 0 | 1 | Bodenfläche | Ku1 | 0 | 0 | NEW | AllplanAttributes - Bezeichnung: PVC Bahnenware Holzoptik; Raumnr. Bauherr: 2.11_A2_02; ash B_Aufbau: B1; ash B_Rutschhemmung: R9
Gipsfaserplatten 2-lagig (BSK) | WUN-H2-E00-074 | CEILING | layer 0.036 m | 1116Dfl0000065963/01 | m² | Trockenbauarbeiten | 1 | 0.036 | 0 | 1 | Deckenfläche |  | 0 | 0 | NEW | 2.5 | AllplanAttributes - Bezeichnung: Gipsfaserplatten 2-lagig (BSK)
Gipsfaserplatten 2-lagig (BSK) | WUN-H2-E00-074 | CEILING | Installationshöhe 0.764 m | 1116Dfl0000065963/02 | m² | Trockenbauarbeiten | 2 | 0.764 | 0 | 1 | Bekleidung | Installationshöhe | 0 | 0 | NEW | 2.5 | Pset_CoveringCommon - FireRating: für korrekte FläVisu; AllplanAttributes - ash_lichte Raumhöhe: 2.500000; OKFF: 0
Gipsfaserplatten 2-lagig (BSK) | WUN-H2-E00-074 | CEILING | A1 0.1 m | 1116Dfl0000065963/03 | m² | Trockenbauarbeiten | 3 | 0.1 | 0 | 1 | Bekleidung | A1 | 0 | 0 | NEW | 2.5 | Pset_CoveringCommon - FireRating: -; AcousticRating: -; AllplanAttributes - ash_lichte Raumhöhe: 2.500000; OKFF: 0
Gipsfaserplatten 2-lagig (BSK) | WUN-H2-E00-074 | CEILING | D1 0.001 m | 1116Dfl0000065963/04 | m² | Maler- und Lackierarbeiten | 4 | 0.001 | 0 | 1 | Bekleidung | D1 | 0 | 0 | NEW | 2.5 | AllplanAttributes - ash_lichte Raumhöhe: 2.500000; OKFF: 0
Gipsfaserplatten 2-lagig (BSK) | WUN-H2-E00-074 | CEILING | layer 0.036 m | 1116Dfl0000065271/01 | m² | Trockenbauarbeiten | 1 | 0.036 | 0 | 1 | Deckenfläche |  | 0 | 0 | NEW | 3.15 | AllplanAttributes - Bezeichnung: Gipsfaserplatten 2-lagig (BSK)
Gipsfaserplatten 2-lagig (BSK) | WUN-H2-E00-074 | CEILING | Installationshöhe 0.114 m | 1116Dfl0000065271/02 | m² | Trockenbauarbeiten | 2 | 0.114 | 0 | 1 | Bekleidung | Installationshöhe | 0 | 0 | NEW | 3.15 | Pset_CoveringCommon - FireRating: -; AcousticRating: -; AllplanAttributes - ash_lichte Raumhöhe: 3.150000
Gipsfaserplatten 2-lagig (BSK) | WUN-H2-E00-074 | CEILING | A1 0.1 m | 1116Dfl0000065271/03 | m² | Trockenbauarbeiten | 3 | 0.1 | 0 | 1 | Bekleidung | A1 | 0 | 0 | NEW | 3.15 | Pset_CoveringCommon - FireRating: -; AcousticRating: -; AllplanAttributes - ash_lichte Raumhöhe: 3.150000
Gipsfaserplatten 2-lagig (BSK) | WUN-H2-E00-074 | CEILING | D1 0.001 m | 1116Dfl0000065271/04 | m² | Maler- und Lackierarbeiten | 4 | 0.001 | 0 | 1 | Bekleidung | D1 | 0 | 0 | NEW | 3.15 | AllplanAttributes - ash_lichte Raumhöhe: 3.150000
Acrobyn | WUN-H2-E00-046 | CLADDING | 84 0.001 m | 1116Sfl0000430863/02 | m² | Maler- und Lackierarbeiten | 2 | 0.001 | 0 | 1 | Seitenfläche | 84 | 0 | 0 | NEW | AllplanAttributes - Bezeichnung: Acrobyn
Acrobyn | WUN-H2-E00-046 | CLADDING | 84 0.001 m | 1116Sfl0000430833/02 | m² | Maler- und Lackierarbeiten | 2 | 0.001 | 0 | 1 | Seitenfläche | 84 | 0 | 0 | NEW | AllplanAttributes - Bezeichnung: Acrobyn
 | WUN-H2-E00-046 | SKIRTINGBOARD |  | 1116Lei0000232045 | m |  |  |  |  | 1 | Leiste |  | 0 | 0 | NEW
PVC Bahnenware Holzoptik | WUN-H2-E00-046 | FLOORING | Ku1 0.2 m | 1116Bfl0000065272/01 | m² | Bodenbelagsarbeiten | 1 | 0.2 | 0 | 1 | Bodenfläche | Ku1 | 0 | 0 | NEW | AllplanAttributes - Bezeichnung: PVC Bahnenware Holzoptik; Raumnr. Bauherr: 2.11_A2_02; ash B_Aufbau: B1; ash B_Rutschhemmung: R9
Gipsfaserplatten 2-lagig (BSK) | WUN-H2-E00-046 | CEILING | layer 0.036 m | 1116Dfl0000065933/01 | m² | Trockenbauarbeiten | 1 | 0.036 | 0 | 1 | Deckenfläche |  | 0 | 0 | NEW | 2.5 | AllplanAttributes - Bezeichnung: Gipsfaserplatten 2-lagig (BSK)
Gipsfaserplatten 2-lagig (BSK) | WUN-H2-E00-046 | CEILING | Installationshöhe 0.764 m | 1116Dfl0000065933/02 | m² | Trockenbauarbeiten | 2 | 0.764 | 0 | 1 | Bekleidung | Installationshöhe | 0 | 0 | NEW | 2.5 | Pset_CoveringCommon - FireRating: für korrekte FläVisu; AllplanAttributes - ash_lichte Raumhöhe: 2.500000; OKFF: 0
Gipsfaserplatten 2-lagig (BSK) | WUN-H2-E00-046 | CEILING | A1 0.1 m | 1116Dfl0000065933/03 | m² | Trockenbauarbeiten | 3 | 0.1 | 0 | 1 | Bekleidung | A1 | 0 | 0 | NEW | 2.5 | Pset_CoveringCommon - FireRating: -; AcousticRating: -; AllplanAttributes - ash_lichte Raumhöhe: 2.500000; OKFF: 0
Gipsfaserplatten 2-lagig (BSK) | WUN-H2-E00-046 | CEILING | D1 0.001 m | 1116Dfl0000065933/04 | m² | Maler- und Lackierarbeiten | 4 | 0.001 | 0 | 1 | Bekleidung | D1 | 0 | 0 | NEW | 2.5 | AllplanAttributes - ash_lichte Raumhöhe: 2.500000; OKFF: 0
Gipsfaserplatten 2-lagig (BSK) | WUN-H2-E00-046 | CEILING | layer 0.036 m | 1116Dfl0000065273/01 | m² | Trockenbauarbeiten | 1 | 0.036 | 0 | 1 | Deckenfläche |  | 0 | 0 | NEW | 3.15 | AllplanAttributes - Bezeichnung: Gipsfaserplatten 2-lagig (BSK)
Gipsfaserplatten 2-lagig (BSK) | WUN-H2-E00-046 | CEILING | Installationshöhe 0.114 m | 1116Dfl0000065273/02 | m² | Trockenbauarbeiten | 2 | 0.114 | 0 | 1 | Bekleidung | Installationshöhe | 0 | 0 | NEW | 3.15 | Pset_CoveringCommon - FireRating: -; AcousticRating: -; AllplanAttributes - ash_lichte Raumhöhe: 3.150000
Gipsfaserplatten 2-lagig (BSK) | WUN-H2-E00-046 | CEILING | A1 0.1 m | 1116Dfl0000065273/03 | m² | Trockenbauarbeiten | 3 | 0.1 | 0 | 1 | Bekleidung | A1 | 0 | 0 | NEW | 3.15 | Pset_CoveringCommon - FireRating: -; AcousticRating: -; AllplanAttributes - ash_lichte Raumhöhe: 3.150000
Gipsfaserplatten 2-lagig (BSK) | WUN-H2-E00-046 | CEILING | D1 0.001 m | 1116Dfl0000065273/04 | m² | Maler- und Lackierarbeiten | 4 | 0.001 | 0 | 1 | Bekleidung | D1 | 0 | 0 | NEW | 3.15 | AllplanAttributes - ash_lichte Raumhöhe: 3.150000
Acrobyn | WUN-H2-E00-093 | CLADDING | 84 0.001 m | 1116Sfl0000430195/02 | m² | Maler- und Lackierarbeiten | 2 | 0.001 | 0 | 1 | Seitenfläche | 84 | 0 | 0 | NEW | AllplanAttributes - Bezeichnung: Acrobyn
PVC Bahnenware Holzoptik | WUN-H2-E00-093 | FLOORING | Ku1 0.2 m | 1116Bfl0000065304/01 | m² | Bodenbelagsarbeiten | 1 | 0.2 | 0 | 1 | Bodenfläche | Ku1 | 0 | 0 | NEW | AllplanAttributes - Bezeichnung: PVC Bahnenware Holzoptik; Raumnr. Bauherr: 2.11_A2_02; ash B_Aufbau: B1; ash B_Rutschhemmung: R9
Gipsfaserplatten 2-lagig (BSK) | WUN-H2-E00-093 | CEILING | layer 0.036 m | 1116Dfl0000065955/01 | m² | Trockenbauarbeiten | 1 | 0.036 | 0 | 1 | Deckenfläche |  | 0 | 0 | NEW | 2.5 | AllplanAttributes - Bezeichnung: Gipsfaserplatten 2-lagig (BSK)
Gipsfaserplatten 2-lagig (BSK) | WUN-H2-E00-093 | CEILING | Installationshöhe 0.764 m | 1116Dfl0000065955/02 | m² | Trockenbauarbeiten | 2 | 0.764 | 0 | 1 | Bekleidung | Installationshöhe | 0 | 0 | NEW | 2.5 | Pset_CoveringCommon - FireRating: für korrekte FläVisu; AllplanAttributes - ash_lichte Raumhöhe: 2.500000; OKFF: 0
Gipsfaserplatten 2-lagig (BSK) | WUN-H2-E00-093 | CEILING | A1 0.1 m | 1116Dfl0000065955/03 | m² | Trockenbauarbeiten | 3 | 0.1 | 0 | 1 | Bekleidung | A1 | 0 | 0 | NEW | 2.5 | Pset_CoveringCommon - FireRating: -; AcousticRating: -; AllplanAttributes - ash_lichte Raumhöhe: 2.500000; OKFF: 0
Gipsfaserplatten 2-lagig (BSK) | WUN-H2-E00-093 | CEILING | D1 0.001 m | 1116Dfl0000065955/04 | m² | Maler- und Lackierarbeiten | 4 | 0.001 | 0 | 1 | Bekleidung | D1 | 0 | 0 | NEW | 2.5 | AllplanAttributes - ash_lichte Raumhöhe: 2.500000; OKFF: 0
Gipsfaserplatten 2-lagig (BSK) | WUN-H2-E00-093 | CEILING | layer 0.036 m | 1116Dfl0000065305/01 | m² | Trockenbauarbeiten | 1 | 0.036 | 0 | 1 | Deckenfläche |  | 0 | 0 | NEW | 3.15 | AllplanAttributes - Bezeichnung: Gipsfaserplatten 2-lagig (BSK)
Gipsfaserplatten 2-lagig (BSK) | WUN-H2-E00-093 | CEILING | Installationshöhe 0.114 m | 1116Dfl0000065305/02 | m² | Trockenbauarbeiten | 2 | 0.114 | 0 | 1 | Bekleidung | Installationshöhe | 0 | 0 | NEW | 3.15 | Pset_CoveringCommon - FireRating: -; AcousticRating: -; AllplanAttributes - ash_lichte Raumhöhe: 3.150000
Gipsfaserplatten 2-lagig (BSK) | WUN-H2-E00-093 | CEILING | A1 0.1 m | 1116Dfl0000065305/03 | m² | Trockenbauarbeiten | 3 | 0.1 | 0 | 1 | Bekleidung | A1 | 0 | 0 | NEW | 3.15 | Pset_CoveringCommon - FireRating: -; AcousticRating: -; AllplanAttributes - ash_lichte Raumhöhe: 3.150000
Gipsfaserplatten 2-lagig (BSK) | WUN-H2-E00-093 | CEILING | D1 0.001 m | 1116Dfl0000065305/04 | m² | Maler- und Lackierarbeiten | 4 | 0.001 | 0 | 1 | Bekleidung | D1 | 0 | 0 | NEW | 3.15 | AllplanAttributes - ash_lichte Raumhöhe: 3.150000
Acrobyn | WUN-H2-E00-094 | CLADDING | 84 0.001 m | 1116Sfl0000430191/02 | m² | Maler- und Lackierarbeiten | 2 | 0.001 | 0 | 1 | Seitenfläche | 84 | 0 | 0 | NEW | AllplanAttributes - Bezeichnung: Acrobyn
Acrobyn | WUN-H2-E00-094 | CLADDING | 84 0.001 m | 1116Sfl0000430187/02 | m² | Maler- und Lackierarbeiten | 2 | 0.001 | 0 | 1 | Seitenfläche | 84 | 0 | 0 | NEW | AllplanAttributes - Bezeichnung: Acrobyn
PVC Bahnenware Holzoptik | WUN-H2-E00-094 | FLOORING | Ku1 0.2 m | 1116Bfl0000065302/01 | m² | Bodenbelagsarbeiten | 1 | 0.2 | 0 | 1 | Bodenfläche | Ku1 | 0 | 0 | NEW | AllplanAttributes - Bezeichnung: PVC Bahnenware Holzoptik; Raumnr. Bauherr: 2.11_A2_02; ash B_Aufbau: B1; ash B_Rutschhemmung: R9
Gipsfaserplatten 2-lagig (BSK) | WUN-H2-E00-094 | CEILING | layer 0.036 m | 1116Dfl0000065303/01 | m² | Trockenbauarbeiten | 1 | 0.036 | 0 | 1 | Deckenfläche |  | 0 | 0 | NEW | 3.15 | AllplanAttributes - Bezeichnung: Gipsfaserplatten 2-lagig (BSK)
Gipsfaserplatten 2-lagig (BSK) | WUN-H2-E00-094 | CEILING | Installationshöhe 0.114 m | 1116Dfl0000065303/02 | m² | Trockenbauarbeiten | 2 | 0.114 | 0 | 1 | Bekleidung | Installationshöhe | 0 | 0 | NEW | 3.15 | Pset_CoveringCommon - FireRating: -; AcousticRating: -; AllplanAttributes - ash_lichte Raumhöhe: 3.150000
Gipsfaserplatten 2-lagig (BSK) | WUN-H2-E00-094 | CEILING | A1 0.1 m | 1116Dfl0000065303/03 | m² | Trockenbauarbeiten | 3 | 0.1 | 0 | 1 | Bekleidung | A1 | 0 | 0 | NEW | 3.15 | Pset_CoveringCommon - FireRating: -; AcousticRating: -; AllplanAttributes - ash_lichte Raumhöhe: 3.150000
Gipsfaserplatten 2-lagig (BSK) | WUN-H2-E00-094 | CEILING | D1 0.001 m | 1116Dfl0000065303/04 | m² | Maler- und Lackierarbeiten | 4 | 0.001 | 0 | 1 | Bekleidung | D1 | 0 | 0 | NEW | 3.15 | AllplanAttributes - ash_lichte Raumhöhe: 3.150000
Gipsfaserplatten 2-lagig (BSK) | WUN-H2-E00-094 | CEILING | layer 0.036 m | 1116Dfl0000065953/01 | m² | Trockenbauarbeiten | 1 | 0.036 | 0 | 1 | Deckenfläche |  | 0 | 0 | NEW | 2.5 | AllplanAttributes - Bezeichnung: Gipsfaserplatten 2-lagig (BSK)
Gipsfaserplatten 2-lagig (BSK) | WUN-H2-E00-094 | CEILING | Installationshöhe 0.764 m | 1116Dfl0000065953/02 | m² | Trockenbauarbeiten | 2 | 0.764 | 0 | 1 | Bekleidung | Installationshöhe | 0 | 0 | NEW | 2.5 | Pset_CoveringCommon - FireRating: für korrekte FläVisu; AllplanAttributes - ash_lichte Raumhöhe: 2.500000; OKFF: 0
Gipsfaserplatten 2-lagig (BSK) | WUN-H2-E00-094 | CEILING | A1 0.1 m | 1116Dfl0000065953/03 | m² | Trockenbauarbeiten | 3 | 0.1 | 0 | 1 | Bekleidung | A1 | 0 | 0 | NEW | 2.5 | Pset_CoveringCommon - FireRating: -; AcousticRating: -; AllplanAttributes - ash_lichte Raumhöhe: 2.500000; OKFF: 0
Gipsfaserplatten 2-lagig (BSK) | WUN-H2-E00-094 | CEILING | D1 0.001 m | 1116Dfl0000065953/04 | m² | Maler- und Lackierarbeiten | 4 | 0.001 | 0 | 1 | Bekleidung | D1 | 0 | 0 | NEW | 2.5 | AllplanAttributes - ash_lichte Raumhöhe: 2.500000; OKFF: 0
Acrobyn | WUN-H2-E00-047 | CLADDING | 84 0.001 m | 1116Sfl0000428676/02 | m² | Maler- und Lackierarbeiten | 2 | 0.001 | 0 | 1 | Seitenfläche | 84 | 0 | 0 | NEW | AllplanAttributes - Bezeichnung: Acrobyn
 | WUN-H2-E00-047 | SKIRTINGBOARD |  | 1116Lei0000232046 | m |  |  |  |  | 1 | Leiste |  | 0 | 0 | NEW
PVC Bahnenware Holzoptik | WUN-H2-E00-047 | FLOORING | Ku1 0.2 m | 1116Bfl0000066565/01 | m² | Bodenbelagsarbeiten | 1 | 0.2 | 0 | 1 | Bodenfläche | Ku1 | 0 | 0 | NEW | AllplanAttributes - Bezeichnung: PVC Bahnenware Holzoptik; Raumnr. Bauherr: 2.11_A2_02; ash B_Aufbau: B1; ash B_Rutschhemmung: R9
Gipsfaserplatten 2-lagig (BSK) | WUN-H2-E00-047 | CEILING | layer 0.036 m | 1116Dfl0000066576/01 | m² | Trockenbauarbeiten | 1 | 0.036 | 0 | 1 | Deckenfläche |  | 0 | 0 | NEW | 2.5 | AllplanAttributes - Bezeichnung: Gipsfaserplatten 2-lagig (BSK)
Gipsfaserplatten 2-lagig (BSK) | WUN-H2-E00-047 | CEILING | Installationshöhe 0.764 m | 1116Dfl0000066576/02 | m² | Trockenbauarbeiten | 2 | 0.764 | 0 | 1 | Bekleidung | Installationshöhe | 0 | 0 | NEW | 2.5 | Pset_CoveringCommon - FireRating: für korrekte FläVisu; AllplanAttributes - ash_lichte Raumhöhe: 2.500000; OKFF: 0
Gipsfaserplatten 2-lagig (BSK) | WUN-H2-E00-047 | CEILING | A1 0.1 m | 1116Dfl0000066576/03 | m² | Trockenbauarbeiten | 3 | 0.1 | 0 | 1 | Bekleidung | A1 | 0 | 0 | NEW | 2.5 | Pset_CoveringCommon - FireRating: -; AcousticRating: -; AllplanAttributes - ash_lichte Raumhöhe: 2.500000; OKFF: 0
Gipsfaserplatten 2-lagig (BSK) | WUN-H2-E00-047 | CEILING | D1 0.001 m | 1116Dfl0000066576/04 | m² | Maler- und Lackierarbeiten | 4 | 0.001 | 0 | 1 | Bekleidung | D1 | 0 | 0 | NEW | 2.5 | AllplanAttributes - ash_lichte Raumhöhe: 2.500000; OKFF: 0
Gipsfaserplatten 2-lagig (BSK) | WUN-H2-E00-047 | CEILING | layer 0.036 m | 1116Dfl0000066564/01 | m² | Trockenbauarbeiten | 1 | 0.036 | 0 | 1 | Deckenfläche |  | 0 | 0 | NEW | 3.15 | AllplanAttributes - Bezeichnung: Gipsfaserplatten 2-lagig (BSK)
Gipsfaserplatten 2-lagig (BSK) | WUN-H2-E00-047 | CEILING | Installationshöhe 0.114 m | 1116Dfl0000066564/02 | m² | Trockenbauarbeiten | 2 | 0.114 | 0 | 1 | Bekleidung | Installationshöhe | 0 | 0 | NEW | 3.15 | Pset_CoveringCommon - FireRating: -; AcousticRating: -; AllplanAttributes - ash_lichte Raumhöhe: 3.150000
Gipsfaserplatten 2-lagig (BSK) | WUN-H2-E00-047 | CEILING | A1 0.1 m | 1116Dfl0000066564/03 | m² | Trockenbauarbeiten | 3 | 0.1 | 0 | 1 | Bekleidung | A1 | 0 | 0 | NEW | 3.15 | Pset_CoveringCommon - FireRating: -; AcousticRating: -; AllplanAttributes - ash_lichte Raumhöhe: 3.150000
Gipsfaserplatten 2-lagig (BSK) | WUN-H2-E00-047 | CEILING | D1 0.001 m | 1116Dfl0000066564/04 | m² | Maler- und Lackierarbeiten | 4 | 0.001 | 0 | 1 | Bekleidung | D1 | 0 | 0 | NEW | 3.15 | AllplanAttributes - ash_lichte Raumhöhe: 3.150000
Acrobyn | WUN-H2-E00-045 | CLADDING | 84 0.001 m | 1116Sfl0000430865/02 | m² | Maler- und Lackierarbeiten | 2 | 0.001 | 0 | 1 | Seitenfläche | 84 | 0 | 0 | NEW | AllplanAttributes - Bezeichnung: Acrobyn
Acrobyn | WUN-H2-E00-045 | CLADDING | 84 0.001 m | 1116Sfl0000430831/02 | m² | Maler- und Lackierarbeiten | 2 | 0.001 | 0 | 1 | Seitenfläche | 84 | 0 | 0 | NEW | AllplanAttributes - Bezeichnung: Acrobyn
 | WUN-H2-E00-045 | SKIRTINGBOARD |  | 1116Lei0000232044 | m |  |  |  |  | 1 | Leiste |  | 0 | 0 | NEW
PVC Bahnenware Holzoptik | WUN-H2-E00-045 | FLOORING | Ku1 0.2 m | 1116Bfl0000065274/01 | m² | Bodenbelagsarbeiten | 1 | 0.2 | 0 | 1 | Bodenfläche | Ku1 | 0 | 0 | NEW | AllplanAttributes - Bezeichnung: PVC Bahnenware Holzoptik; Raumnr. Bauherr: 2.11_A2_02; ash B_Aufbau: B1; ash B_Rutschhemmung: R9
Gipsfaserplatten 2-lagig (BSK) | WUN-H2-E00-045 | CEILING | layer 0.036 m | 1116Dfl0000065931/01 | m² | Trockenbauarbeiten | 1 | 0.036 | 0 | 1 | Deckenfläche |  | 0 | 0 | NEW | 2.5 | AllplanAttributes - Bezeichnung: Gipsfaserplatten 2-lagig (BSK)
Gipsfaserplatten 2-lagig (BSK) | WUN-H2-E00-045 | CEILING | Installationshöhe 0.764 m | 1116Dfl0000065931/02 | m² | Trockenbauarbeiten | 2 | 0.764 | 0 | 1 | Bekleidung | Installationshöhe | 0 | 0 | NEW | 2.5 | Pset_CoveringCommon - FireRating: für korrekte FläVisu; AllplanAttributes - ash_lichte Raumhöhe: 2.500000; OKFF: 0
Gipsfaserplatten 2-lagig (BSK) | WUN-H2-E00-045 | CEILING | A1 0.1 m | 1116Dfl0000065931/03 | m² | Trockenbauarbeiten | 3 | 0.1 | 0 | 1 | Bekleidung | A1 | 0 | 0 | NEW | 2.5 | Pset_CoveringCommon - FireRating: -; AcousticRating: -; AllplanAttributes - ash_lichte Raumhöhe: 2.500000; OKFF: 0
Gipsfaserplatten 2-lagig (BSK) | WUN-H2-E00-045 | CEILING | D1 0.001 m | 1116Dfl0000065931/04 | m² | Maler- und Lackierarbeiten | 4 | 0.001 | 0 | 1 | Bekleidung | D1 | 0 | 0 | NEW | 2.5 | AllplanAttributes - ash_lichte Raumhöhe: 2.500000; OKFF: 0
Gipsfaserplatten 2-lagig (BSK) | WUN-H2-E00-045 | CEILING | layer 0.036 m | 1116Dfl0000065275/01 | m² | Trockenbauarbeiten | 1 | 0.036 | 0 | 1 | Deckenfläche |  | 0 | 0 | NEW | 3.15 | AllplanAttributes - Bezeichnung: Gipsfaserplatten 2-lagig (BSK)
Gipsfaserplatten 2-lagig (BSK) | WUN-H2-E00-045 | CEILING | Installationshöhe 0.114 m | 1116Dfl0000065275/02 | m² | Trockenbauarbeiten | 2 | 0.114 | 0 | 1 | Bekleidung | Installationshöhe | 0 | 0 | NEW | 3.15 | Pset_CoveringCommon - FireRating: -; AcousticRating: -; AllplanAttributes - ash_lichte Raumhöhe: 3.150000
Gipsfaserplatten 2-lagig (BSK) | WUN-H2-E00-045 | CEILING | A1 0.1 m | 1116Dfl0000065275/03 | m² | Trockenbauarbeiten | 3 | 0.1 | 0 | 1 | Bekleidung | A1 | 0 | 0 | NEW | 3.15 | Pset_CoveringCommon - FireRating: -; AcousticRating: -; AllplanAttributes - ash_lichte Raumhöhe: 3.150000
Gipsfaserplatten 2-lagig (BSK) | WUN-H2-E00-045 | CEILING | D1 0.001 m | 1116Dfl0000065275/04 | m² | Maler- und Lackierarbeiten | 4 | 0.001 | 0 | 1 | Bekleidung | D1 | 0 | 0 | NEW | 3.15 | AllplanAttributes - ash_lichte Raumhöhe: 3.150000
Acrobyn | WUN-H2-E00-044 | CLADDING | 84 0.001 m | 1116Sfl0000430829/02 | m² | Maler- und Lackierarbeiten | 2 | 0.001 | 0 | 1 | Seitenfläche | 84 | 0 | 0 | NEW | AllplanAttributes - Bezeichnung: Acrobyn
 | WUN-H2-E00-044 | SKIRTINGBOARD |  | 1116Lei0000232013 | m |  |  |  |  | 1 | Leiste |  | 0 | 0 | NEW
PVC Bahnenware Holzoptik | WUN-H2-E00-044 | FLOORING | Ku1 0.2 m | 1116Bfl0000065292/01 | m² | Bodenbelagsarbeiten | 1 | 0.2 | 0 | 1 | Bodenfläche | Ku1 | 0 | 0 | NEW | AllplanAttributes - Bezeichnung: PVC Bahnenware Holzoptik; Raumnr. Bauherr: 2.11_A2_02; ash B_Aufbau: B1; ash B_Rutschhemmung: R9
Gipsfaserplatten 2-lagig (BSK) | WUN-H2-E00-044 | CEILING | layer 0.036 m | 1116Dfl0000065929/01 | m² | Trockenbauarbeiten | 1 | 0.036 | 0 | 1 | Deckenfläche |  | 0 | 0 | NEW | 2.5 | AllplanAttributes - Bezeichnung: Gipsfaserplatten 2-lagig (BSK)
Gipsfaserplatten 2-lagig (BSK) | WUN-H2-E00-044 | CEILING | Installationshöhe 0.764 m | 1116Dfl0000065929/02 | m² | Trockenbauarbeiten | 2 | 0.764 | 0 | 1 | Bekleidung | Installationshöhe | 0 | 0 | NEW | 2.5 | Pset_CoveringCommon - FireRating: für korrekte FläVisu; AllplanAttributes - ash_lichte Raumhöhe: 2.500000; OKFF: 0
Gipsfaserplatten 2-lagig (BSK) | WUN-H2-E00-044 | CEILING | A1 0.1 m | 1116Dfl0000065929/03 | m² | Trockenbauarbeiten | 3 | 0.1 | 0 | 1 | Bekleidung | A1 | 0 | 0 | NEW | 2.5 | Pset_CoveringCommon - FireRating: -; AcousticRating: -; AllplanAttributes - ash_lichte Raumhöhe: 2.500000; OKFF: 0
Gipsfaserplatten 2-lagig (BSK) | WUN-H2-E00-044 | CEILING | D1 0.001 m | 1116Dfl0000065929/04 | m² | Maler- und Lackierarbeiten | 4 | 0.001 | 0 | 1 | Bekleidung | D1 | 0 | 0 | NEW | 2.5 | AllplanAttributes - ash_lichte Raumhöhe: 2.500000; OKFF: 0
Gipsfaserplatten 2-lagig (BSK) | WUN-H2-E00-044 | CEILING | layer 0.036 m | 1116Dfl0000065293/01 | m² | Trockenbauarbeiten | 1 | 0.036 | 0 | 1 | Deckenfläche |  | 0 | 0 | NEW | 3.15 | AllplanAttributes - Bezeichnung: Gipsfaserplatten 2-lagig (BSK)
Gipsfaserplatten 2-lagig (BSK) | WUN-H2-E00-044 | CEILING | Installationshöhe 0.114 m | 1116Dfl0000065293/02 | m² | Trockenbauarbeiten | 2 | 0.114 | 0 | 1 | Bekleidung | Installationshöhe | 0 | 0 | NEW | 3.15 | Pset_CoveringCommon - FireRating: -; AcousticRating: -; AllplanAttributes - ash_lichte Raumhöhe: 3.150000
Gipsfaserplatten 2-lagig (BSK) | WUN-H2-E00-044 | CEILING | A1 0.1 m | 1116Dfl0000065293/03 | m² | Trockenbauarbeiten | 3 | 0.1 | 0 | 1 | Bekleidung | A1 | 0 | 0 | NEW | 3.15 | Pset_CoveringCommon - FireRating: -; AcousticRating: -; AllplanAttributes - ash_lichte Raumhöhe: 3.150000
Gipsfaserplatten 2-lagig (BSK) | WUN-H2-E00-044 | CEILING | D1 0.001 m | 1116Dfl0000065293/04 | m² | Maler- und Lackierarbeiten | 4 | 0.001 | 0 | 1 | Bekleidung | D1 | 0 | 0 | NEW | 3.15 | AllplanAttributes - ash_lichte Raumhöhe: 3.150000
Acrobyn | WUN-H2-E00-043 | CLADDING | 84 0.001 m | 1116Sfl0000430867/02 | m² | Maler- und Lackierarbeiten | 2 | 0.001 | 0 | 1 | Seitenfläche | 84 | 0 | 0 | NEW | AllplanAttributes - Bezeichnung: Acrobyn
Acrobyn | WUN-H2-E00-043 | CLADDING | 84 0.001 m | 1116Sfl0000430532/02 | m² | Maler- und Lackierarbeiten | 2 | 0.001 | 0 | 1 | Seitenfläche | 84 | 0 | 0 | NEW | AllplanAttributes - Bezeichnung: Acrobyn
 | WUN-H2-E00-043 | SKIRTINGBOARD |  | 1116Lei0000232012 | m |  |  |  |  | 1 | Leiste |  | 0 | 0 | NEW
PVC Bahnenware Holzoptik | WUN-H2-E00-043 | FLOORING | Ku1 0.2 m | 1116Bfl0000065322/01 | m² | Bodenbelagsarbeiten | 1 | 0.2 | 0 | 1 | Bodenfläche | Ku1 | 0 | 0 | NEW | AllplanAttributes - Bezeichnung: PVC Bahnenware Holzoptik; Raumnr. Bauherr: 2.11_A2_02; ash B_Aufbau: B1; ash B_Rutschhemmung: R9
Gipsfaserplatten 2-lagig (BSK) | WUN-H2-E00-043 | CEILING | layer 0.036 m | 1116Dfl0000065925/01 | m² | Trockenbauarbeiten | 1 | 0.036 | 0 | 1 | Deckenfläche |  | 0 | 0 | NEW | 2.5 | AllplanAttributes - Bezeichnung: Gipsfaserplatten 2-lagig (BSK)
Gipsfaserplatten 2-lagig (BSK) | WUN-H2-E00-043 | CEILING | Installationshöhe 0.764 m | 1116Dfl0000065925/02 | m² | Trockenbauarbeiten | 2 | 0.764 | 0 | 1 | Bekleidung | Installationshöhe | 0 | 0 | NEW | 2.5 | Pset_CoveringCommon - FireRating: für korrekte FläVisu; AllplanAttributes - ash_lichte Raumhöhe: 2.500000; OKFF: 0
Gipsfaserplatten 2-lagig (BSK) | WUN-H2-E00-043 | CEILING | A1 0.1 m | 1116Dfl0000065925/03 | m² | Trockenbauarbeiten | 3 | 0.1 | 0 | 1 | Bekleidung | A1 | 0 | 0 | NEW | 2.5 | Pset_CoveringCommon - FireRating: -; AcousticRating: -; AllplanAttributes - ash_lichte Raumhöhe: 2.500000; OKFF: 0
Gipsfaserplatten 2-lagig (BSK) | WUN-H2-E00-043 | CEILING | D1 0.001 m | 1116Dfl0000065925/04 | m² | Maler- und Lackierarbeiten | 4 | 0.001 | 0 | 1 | Bekleidung | D1 | 0 | 0 | NEW | 2.5 | AllplanAttributes - ash_lichte Raumhöhe: 2.500000; OKFF: 0
Gipsfaserplatten 2-lagig (BSK) | WUN-H2-E00-043 | CEILING | layer 0.036 m | 1116Dfl0000065323/01 | m² | Trockenbauarbeiten | 1 | 0.036 | 0 | 1 | Deckenfläche |  | 0 | 0 | NEW | 3.15 | AllplanAttributes - Bezeichnung: Gipsfaserplatten 2-lagig (BSK)
Gipsfaserplatten 2-lagig (BSK) | WUN-H2-E00-043 | CEILING | Installationshöhe 0.114 m | 1116Dfl0000065323/02 | m² | Trockenbauarbeiten | 2 | 0.114 | 0 | 1 | Bekleidung | Installationshöhe | 0 | 0 | NEW | 3.15 | Pset_CoveringCommon - FireRating: -; AcousticRating: -; AllplanAttributes - ash_lichte Raumhöhe: 3.150000
Gipsfaserplatten 2-lagig (BSK) | WUN-H2-E00-043 | CEILING | A1 0.1 m | 1116Dfl0000065323/03 | m² | Trockenbauarbeiten | 3 | 0.1 | 0 | 1 | Bekleidung | A1 | 0 | 0 | NEW | 3.15 | Pset_CoveringCommon - FireRating: -; AcousticRating: -; AllplanAttributes - ash_lichte Raumhöhe: 3.150000
Gipsfaserplatten 2-lagig (BSK) | WUN-H2-E00-043 | CEILING | D1 0.001 m | 1116Dfl0000065323/04 | m² | Maler- und Lackierarbeiten | 4 | 0.001 | 0 | 1 | Bekleidung | D1 | 0 | 0 | NEW | 3.15 | AllplanAttributes - ash_lichte Raumhöhe: 3.150000
Acrobyn | WUN-H2-E00-068 | CLADDING | 84 0.001 m | 1116Sfl0000428968/02 | m² | Maler- und Lackierarbeiten | 2 | 0.001 | 0 | 1 | Seitenfläche | 84 | 0 | 0 | NEW | AllplanAttributes - Bezeichnung: Acrobyn
PVC Bahnenware Holzoptik | WUN-H2-E00-068 | FLOORING | Ku1 0.2 m | 1116Bfl0000066832/01 | m² | Bodenbelagsarbeiten | 1 | 0.2 | 0 | 1 | Bodenfläche | Ku1 | 0 | 0 | NEW | AllplanAttributes - Bezeichnung: PVC Bahnenware Holzoptik; Raumnr. Bauherr: 2.11_A2_02; ash B_Aufbau: B1; ash B_Rutschhemmung: R9
Gipsfaserplatten 2-lagig (BSK) | WUN-H2-E00-068 | CEILING | layer 0.036 m | 1116Dfl0000883632/01 | m² | Trockenbauarbeiten | 1 | 0.036 | 0 | 1 | Deckenfläche |  | 0 | 0 | NEW | 2.5 | AllplanAttributes - Bezeichnung: Gipsfaserplatten 2-lagig (BSK)
Gipsfaserplatten 2-lagig (BSK) | WUN-H2-E00-068 | CEILING | Installationshöhe 0.764 m | 1116Dfl0000883632/02 | m² | Trockenbauarbeiten | 2 | 0.764 | 0 | 1 | Bekleidung | Installationshöhe | 0 | 0 | NEW | 2.5 | Pset_CoveringCommon - FireRating: für korrekte FläVisu; AllplanAttributes - ash_lichte Raumhöhe: 2.500000; OKFF: 0
Gipsfaserplatten 2-lagig (BSK) | WUN-H2-E00-068 | CEILING | A1 0.1 m | 1116Dfl0000883632/03 | m² | Trockenbauarbeiten | 3 | 0.1 | 0 | 1 | Bekleidung | A1 | 0 | 0 | NEW | 2.5 | Pset_CoveringCommon - FireRating: -; AcousticRating: -; AllplanAttributes - ash_lichte Raumhöhe: 2.500000; OKFF: 0
Gipsfaserplatten 2-lagig (BSK) | WUN-H2-E00-068 | CEILING | D1 0.001 m | 1116Dfl0000883632/04 | m² | Maler- und Lackierarbeiten | 4 | 0.001 | 0 | 1 | Bekleidung | D1 | 0 | 0 | NEW | 2.5 | AllplanAttributes - ash_lichte Raumhöhe: 2.500000; OKFF: 0
Gipsfaserplatten 2-lagig (BSK) | WUN-H2-E00-068 | CEILING | layer 0.036 m | 1116Dfl0000066833/01 | m² | Trockenbauarbeiten | 1 | 0.036 | 0 | 1 | Deckenfläche |  | 0 | 0 | NEW | 3.15 | AllplanAttributes - Bezeichnung: Gipsfaserplatten 2-lagig (BSK)
Gipsfaserplatten 2-lagig (BSK) | WUN-H2-E00-068 | CEILING | Installationshöhe 0.114 m | 1116Dfl0000066833/02 | m² | Trockenbauarbeiten | 2 | 0.114 | 0 | 1 | Bekleidung | Installationshöhe | 0 | 0 | NEW | 3.15 | Pset_CoveringCommon - FireRating: -; AcousticRating: -; AllplanAttributes - ash_lichte Raumhöhe: 3.150000
Gipsfaserplatten 2-lagig (BSK) | WUN-H2-E00-068 | CEILING | A1 0.1 m | 1116Dfl0000066833/03 | m² | Trockenbauarbeiten | 3 | 0.1 | 0 | 1 | Bekleidung | A1 | 0 | 0 | NEW | 3.15 | Pset_CoveringCommon - FireRating: -; AcousticRating: -; AllplanAttributes - ash_lichte Raumhöhe: 3.150000
Gipsfaserplatten 2-lagig (BSK) | WUN-H2-E00-068 | CEILING | D1 0.001 m | 1116Dfl0000066833/04 | m² | Maler- und Lackierarbeiten | 4 | 0.001 | 0 | 1 | Bekleidung | D1 | 0 | 0 | NEW | 3.15 | AllplanAttributes - ash_lichte Raumhöhe: 3.150000
Acrobyn | WUN-H2-E00-069 | CLADDING | 84 0.001 m | 1116Sfl0000430835/02 | m² | Maler- und Lackierarbeiten | 2 | 0.001 | 0 | 1 | Seitenfläche | 84 | 0 | 0 | NEW | AllplanAttributes - Bezeichnung: Acrobyn
Acrobyn | WUN-H2-E00-069 | CLADDING | 84 0.001 m | 1116Sfl0000430861/02 | m² | Maler- und Lackierarbeiten | 2 | 0.001 | 0 | 1 | Seitenfläche | 84 | 0 | 0 | NEW | AllplanAttributes - Bezeichnung: Acrobyn
PVC Bahnenware Holzoptik | WUN-H2-E00-069 | FLOORING | Ku1 0.2 m | 1116Bfl0000065288/01 | m² | Bodenbelagsarbeiten | 1 | 0.2 | 0 | 1 | Bodenfläche | Ku1 | 0 | 0 | NEW | AllplanAttributes - Bezeichnung: PVC Bahnenware Holzoptik; Raumnr. Bauherr: 2.11_A2_02; ash B_Aufbau: B1; ash B_Rutschhemmung: R9
Gipsfaserplatten 2-lagig (BSK) | WUN-H2-E00-069 | CEILING | layer 0.036 m | 1116Dfl0000065971/01 | m² | Trockenbauarbeiten | 1 | 0.036 | 0 | 1 | Deckenfläche |  | 0 | 0 | NEW | 2.5 | AllplanAttributes - Bezeichnung: Gipsfaserplatten 2-lagig (BSK)
Gipsfaserplatten 2-lagig (BSK) | WUN-H2-E00-069 | CEILING | Installationshöhe 0.764 m | 1116Dfl0000065971/02 | m² | Trockenbauarbeiten | 2 | 0.764 | 0 | 1 | Bekleidung | Installationshöhe | 0 | 0 | NEW | 2.5 | Pset_CoveringCommon - FireRating: für korrekte FläVisu; AllplanAttributes - ash_lichte Raumhöhe: 2.500000; OKFF: 0
Gipsfaserplatten 2-lagig (BSK) | WUN-H2-E00-069 | CEILING | A1 0.1 m | 1116Dfl0000065971/03 | m² | Trockenbauarbeiten | 3 | 0.1 | 0 | 1 | Bekleidung | A1 | 0 | 0 | NEW | 2.5 | Pset_CoveringCommon - FireRating: -; AcousticRating: -; AllplanAttributes - ash_lichte Raumhöhe: 2.500000; OKFF: 0
Gipsfaserplatten 2-lagig (BSK) | WUN-H2-E00-069 | CEILING | D1 0.001 m | 1116Dfl0000065971/04 | m² | Maler- und Lackierarbeiten | 4 | 0.001 | 0 | 1 | Bekleidung | D1 | 0 | 0 | NEW | 2.5 | AllplanAttributes - ash_lichte Raumhöhe: 2.500000; OKFF: 0
Gipsfaserplatten 2-lagig (BSK) | WUN-H2-E00-069 | CEILING | layer 0.036 m | 1116Dfl0000065289/01 | m² | Trockenbauarbeiten | 1 | 0.036 | 0 | 1 | Deckenfläche |  | 0 | 0 | NEW | 3.15 | AllplanAttributes - Bezeichnung: Gipsfaserplatten 2-lagig (BSK)
Gipsfaserplatten 2-lagig (BSK) | WUN-H2-E00-069 | CEILING | Installationshöhe 0.114 m | 1116Dfl0000065289/02 | m² | Trockenbauarbeiten | 2 | 0.114 | 0 | 1 | Bekleidung | Installationshöhe | 0 | 0 | NEW | 3.15 | Pset_CoveringCommon - FireRating: -; AcousticRating: -; AllplanAttributes - ash_lichte Raumhöhe: 3.150000
Gipsfaserplatten 2-lagig (BSK) | WUN-H2-E00-069 | CEILING | A1 0.1 m | 1116Dfl0000065289/03 | m² | Trockenbauarbeiten | 3 | 0.1 | 0 | 1 | Bekleidung | A1 | 0 | 0 | NEW | 3.15 | Pset_CoveringCommon - FireRating: -; AcousticRating: -; AllplanAttributes - ash_lichte Raumhöhe: 3.150000
Gipsfaserplatten 2-lagig (BSK) | WUN-H2-E00-069 | CEILING | D1 0.001 m | 1116Dfl0000065289/04 | m² | Maler- und Lackierarbeiten | 4 | 0.001 | 0 | 1 | Bekleidung | D1 | 0 | 0 | NEW | 3.15 | AllplanAttributes - ash_lichte Raumhöhe: 3.150000
Acrobyn | WUN-H2-E00-070 | CLADDING | 84 0.001 m | 1116Sfl0000430837/02 | m² | Maler- und Lackierarbeiten | 2 | 0.001 | 0 | 1 | Seitenfläche | 84 | 0 | 0 | NEW | AllplanAttributes - Bezeichnung: Acrobyn
Acrobyn | WUN-H2-E00-070 | CLADDING | 84 0.001 m | 1116Sfl0000430859/02 | m² | Maler- und Lackierarbeiten | 2 | 0.001 | 0 | 1 | Seitenfläche | 84 | 0 | 0 | NEW | AllplanAttributes - Bezeichnung: Acrobyn
PVC Bahnenware Holzoptik | WUN-H2-E00-070 | FLOORING | Ku1 0.2 m | 1116Bfl0000065298/01 | m² | Bodenbelagsarbeiten | 1 | 0.2 | 0 | 1 | Bodenfläche | Ku1 | 0 | 0 | NEW | AllplanAttributes - Bezeichnung: PVC Bahnenware Holzoptik; Raumnr. Bauherr: 2.11_A2_02; ash B_Aufbau: B1; ash B_Rutschhemmung: R9
Gipsfaserplatten 2-lagig (BSK) | WUN-H2-E00-070 | CEILING | layer 0.036 m | 1116Dfl0000065977/01 | m² | Trockenbauarbeiten | 1 | 0.036 | 0 | 1 | Deckenfläche |  | 0 | 0 | NEW | 2.5 | AllplanAttributes - Bezeichnung: Gipsfaserplatten 2-lagig (BSK)
Gipsfaserplatten 2-lagig (BSK) | WUN-H2-E00-070 | CEILING | Installationshöhe 0.764 m | 1116Dfl0000065977/02 | m² | Trockenbauarbeiten | 2 | 0.764 | 0 | 1 | Bekleidung | Installationshöhe | 0 | 0 | NEW | 2.5 | Pset_CoveringCommon - FireRating: für korrekte FläVisu; AllplanAttributes - ash_lichte Raumhöhe: 2.500000; OKFF: 0
Gipsfaserplatten 2-lagig (BSK) | WUN-H2-E00-070 | CEILING | A1 0.1 m | 1116Dfl0000065977/03 | m² | Trockenbauarbeiten | 3 | 0.1 | 0 | 1 | Bekleidung | A1 | 0 | 0 | NEW | 2.5 | Pset_CoveringCommon - FireRating: -; AcousticRating: -; AllplanAttributes - ash_lichte Raumhöhe: 2.500000; OKFF: 0
Gipsfaserplatten 2-lagig (BSK) | WUN-H2-E00-070 | CEILING | D1 0.001 m | 1116Dfl0000065977/04 | m² | Maler- und Lackierarbeiten | 4 | 0.001 | 0 | 1 | Bekleidung | D1 | 0 | 0 | NEW | 2.5 | AllplanAttributes - ash_lichte Raumhöhe: 2.500000; OKFF: 0
Gipsfaserplatten 2-lagig (BSK) | WUN-H2-E00-070 | CEILING | layer 0.036 m | 1116Dfl0000065299/01 | m² | Trockenbauarbeiten | 1 | 0.036 | 0 | 1 | Deckenfläche |  | 0 | 0 | NEW | 3.15 | AllplanAttributes - Bezeichnung: Gipsfaserplatten 2-lagig (BSK)
Gipsfaserplatten 2-lagig (BSK) | WUN-H2-E00-070 | CEILING | Installationshöhe 0.114 m | 1116Dfl0000065299/02 | m² | Trockenbauarbeiten | 2 | 0.114 | 0 | 1 | Bekleidung | Installationshöhe | 0 | 0 | NEW | 3.15 | Pset_CoveringCommon - FireRating: -; AcousticRating: -; AllplanAttributes - ash_lichte Raumhöhe: 3.150000
Gipsfaserplatten 2-lagig (BSK) | WUN-H2-E00-070 | CEILING | A1 0.1 m | 1116Dfl0000065299/03 | m² | Trockenbauarbeiten | 3 | 0.1 | 0 | 1 | Bekleidung | A1 | 0 | 0 | NEW | 3.15 | Pset_CoveringCommon - FireRating: -; AcousticRating: -; AllplanAttributes - ash_lichte Raumhöhe: 3.150000
Gipsfaserplatten 2-lagig (BSK) | WUN-H2-E00-070 | CEILING | D1 0.001 m | 1116Dfl0000065299/04 | m² | Maler- und Lackierarbeiten | 4 | 0.001 | 0 | 1 | Bekleidung | D1 | 0 | 0 | NEW | 3.15 | AllplanAttributes - ash_lichte Raumhöhe: 3.150000
Acrobyn | WUN-H2-E00-071 | CLADDING | 84 0.001 m | 1116Sfl0000430857/02 | m² | Maler- und Lackierarbeiten | 2 | 0.001 | 0 | 1 | Seitenfläche | 84 | 0 | 0 | NEW | AllplanAttributes - Bezeichnung: Acrobyn
PVC Bahnenware Holzoptik | WUN-H2-E00-071 | FLOORING | Ku1 0.2 m | 1116Bfl0000065296/01 | m² | Bodenbelagsarbeiten | 1 | 0.2 | 0 | 1 | Bodenfläche | Ku1 | 0 | 0 | NEW | AllplanAttributes - Bezeichnung: PVC Bahnenware Holzoptik; Raumnr. Bauherr: 2.11_A2_02; ash B_Aufbau: B1; ash B_Rutschhemmung: R9
Gipsfaserplatten 2-lagig (BSK) | WUN-H2-E00-071 | CEILING | layer 0.036 m | 1116Dfl0000065297/01 | m² | Trockenbauarbeiten | 1 | 0.036 | 0 | 1 | Deckenfläche |  | 0 | 0 | NEW | 3.15 | AllplanAttributes - Bezeichnung: Gipsfaserplatten 2-lagig (BSK)
Gipsfaserplatten 2-lagig (BSK) | WUN-H2-E00-071 | CEILING | Installationshöhe 0.114 m | 1116Dfl0000065297/02 | m² | Trockenbauarbeiten | 2 | 0.114 | 0 | 1 | Bekleidung | Installationshöhe | 0 | 0 | NEW | 3.15 | Pset_CoveringCommon - FireRating: -; AcousticRating: -; AllplanAttributes - ash_lichte Raumhöhe: 3.150000
Gipsfaserplatten 2-lagig (BSK) | WUN-H2-E00-071 | CEILING | A1 0.1 m | 1116Dfl0000065297/03 | m² | Trockenbauarbeiten | 3 | 0.1 | 0 | 1 | Bekleidung | A1 | 0 | 0 | NEW | 3.15 | Pset_CoveringCommon - FireRating: -; AcousticRating: -; AllplanAttributes - ash_lichte Raumhöhe: 3.150000
Gipsfaserplatten 2-lagig (BSK) | WUN-H2-E00-071 | CEILING | D1 0.001 m | 1116Dfl0000065297/04 | m² | Maler- und Lackierarbeiten | 4 | 0.001 | 0 | 1 | Bekleidung | D1 | 0 | 0 | NEW | 3.15 | AllplanAttributes - ash_lichte Raumhöhe: 3.150000
Gipsfaserplatten 2-lagig (BSK) | WUN-H2-E00-071 | CEILING | layer 0.036 m | 1116Dfl0000065969/01 | m² | Trockenbauarbeiten | 1 | 0.036 | 0 | 1 | Deckenfläche |  | 0 | 0 | NEW | 2.5 | AllplanAttributes - Bezeichnung: Gipsfaserplatten 2-lagig (BSK)
Gipsfaserplatten 2-lagig (BSK) | WUN-H2-E00-071 | CEILING | Installationshöhe 0.764 m | 1116Dfl0000065969/02 | m² | Trockenbauarbeiten | 2 | 0.764 | 0 | 1 | Bekleidung | Installationshöhe | 0 | 0 | NEW | 2.5 | Pset_CoveringCommon - FireRating: für korrekte FläVisu; AllplanAttributes - ash_lichte Raumhöhe: 2.500000; OKFF: 0
Gipsfaserplatten 2-lagig (BSK) | WUN-H2-E00-071 | CEILING | A1 0.1 m | 1116Dfl0000065969/03 | m² | Trockenbauarbeiten | 3 | 0.1 | 0 | 1 | Bekleidung | A1 | 0 | 0 | NEW | 2.5 | Pset_CoveringCommon - FireRating: -; AcousticRating: -; AllplanAttributes - ash_lichte Raumhöhe: 2.500000; OKFF: 0
Gipsfaserplatten 2-lagig (BSK) | WUN-H2-E00-071 | CEILING | D1 0.001 m | 1116Dfl0000065969/04 | m² | Maler- und Lackierarbeiten | 4 | 0.001 | 0 | 1 | Bekleidung | D1 | 0 | 0 | NEW | 2.5 | AllplanAttributes - ash_lichte Raumhöhe: 2.500000; OKFF: 0
Acrobyn | WUN-H2-E00-072 | CLADDING | 84 0.001 m | 1116Sfl0000430839/02 | m² | Maler- und Lackierarbeiten | 2 | 0.001 | 0 | 1 | Seitenfläche | 84 | 0 | 0 | NEW | AllplanAttributes - Bezeichnung: Acrobyn
Acrobyn | WUN-H2-E00-072 | CLADDING | 84 0.001 m | 1116Sfl0000430851/02 | m² | Maler- und Lackierarbeiten | 2 | 0.001 | 0 | 1 | Seitenfläche | 84 | 0 | 0 | NEW | AllplanAttributes - Bezeichnung: Acrobyn
PVC Bahnenware Holzoptik | WUN-H2-E00-072 | FLOORING | Ku1 0.2 m | 1116Bfl0000065294/01 | m² | Bodenbelagsarbeiten | 1 | 0.2 | 0 | 1 | Bodenfläche | Ku1 | 0 | 0 | NEW | AllplanAttributes - Bezeichnung: PVC Bahnenware Holzoptik; Raumnr. Bauherr: 2.11_A2_02; ash B_Aufbau: B1; ash B_Rutschhemmung: R9
Gipsfaserplatten 2-lagig (BSK) | WUN-H2-E00-072 | CEILING | layer 0.036 m | 1116Dfl0000065295/01 | m² | Trockenbauarbeiten | 1 | 0.036 | 0 | 1 | Deckenfläche |  | 0 | 0 | NEW | 3.15 | AllplanAttributes - Bezeichnung: Gipsfaserplatten 2-lagig (BSK)
Gipsfaserplatten 2-lagig (BSK) | WUN-H2-E00-072 | CEILING | Installationshöhe 0.114 m | 1116Dfl0000065295/02 | m² | Trockenbauarbeiten | 2 | 0.114 | 0 | 1 | Bekleidung | Installationshöhe | 0 | 0 | NEW | 3.15 | Pset_CoveringCommon - FireRating: -; AcousticRating: -; AllplanAttributes - ash_lichte Raumhöhe: 3.150000
Gipsfaserplatten 2-lagig (BSK) | WUN-H2-E00-072 | CEILING | A1 0.1 m | 1116Dfl0000065295/03 | m² | Trockenbauarbeiten | 3 | 0.1 | 0 | 1 | Bekleidung | A1 | 0 | 0 | NEW | 3.15 | Pset_CoveringCommon - FireRating: -; AcousticRating: -; AllplanAttributes - ash_lichte Raumhöhe: 3.150000
Gipsfaserplatten 2-lagig (BSK) | WUN-H2-E00-072 | CEILING | D1 0.001 m | 1116Dfl0000065295/04 | m² | Maler- und Lackierarbeiten | 4 | 0.001 | 0 | 1 | Bekleidung | D1 | 0 | 0 | NEW | 3.15 | AllplanAttributes - ash_lichte Raumhöhe: 3.150000
Gipsfaserplatten 2-lagig (BSK) | WUN-H2-E00-072 | CEILING | layer 0.036 m | 1116Dfl0000065967/01 | m² | Trockenbauarbeiten | 1 | 0.036 | 0 | 1 | Deckenfläche |  | 0 | 0 | NEW | 2.5 | AllplanAttributes - Bezeichnung: Gipsfaserplatten 2-lagig (BSK)
Gipsfaserplatten 2-lagig (BSK) | WUN-H2-E00-072 | CEILING | Installationshöhe 0.764 m | 1116Dfl0000065967/02 | m² | Trockenbauarbeiten | 2 | 0.764 | 0 | 1 | Bekleidung | Installationshöhe | 0 | 0 | NEW | 2.5 | Pset_CoveringCommon - FireRating: für korrekte FläVisu; AllplanAttributes - ash_lichte Raumhöhe: 2.500000; OKFF: 0
Gipsfaserplatten 2-lagig (BSK) | WUN-H2-E00-072 | CEILING | A1 0.1 m | 1116Dfl0000065967/03 | m² | Trockenbauarbeiten | 3 | 0.1 | 0 | 1 | Bekleidung | A1 | 0 | 0 | NEW | 2.5 | Pset_CoveringCommon - FireRating: -; AcousticRating: -; AllplanAttributes - ash_lichte Raumhöhe: 2.500000; OKFF: 0
Gipsfaserplatten 2-lagig (BSK) | WUN-H2-E00-072 | CEILING | D1 0.001 m | 1116Dfl0000065967/04 | m² | Maler- und Lackierarbeiten | 4 | 0.001 | 0 | 1 | Bekleidung | D1 | 0 | 0 | NEW | 2.5 | AllplanAttributes - ash_lichte Raumhöhe: 2.500000; OKFF: 0
Acrobyn | WUN-H2-E00-073 | CLADDING | 84 0.001 m | 1116Sfl0000430841/02 | m² | Maler- und Lackierarbeiten | 2 | 0.001 | 0 | 1 | Seitenfläche | 84 | 0 | 0 | NEW | AllplanAttributes - Bezeichnung: Acrobyn
Acrobyn | WUN-H2-E00-073 | CLADDING | 84 0.001 m | 1116Sfl0000430847/02 | m² | Maler- und Lackierarbeiten | 2 | 0.001 | 0 | 1 | Seitenfläche | 84 | 0 | 0 | NEW | AllplanAttributes - Bezeichnung: Acrobyn
PVC Bahnenware Holzoptik | WUN-H2-E00-073 | FLOORING | Ku1 0.2 m | 1116Bfl0000065300/01 | m² | Bodenbelagsarbeiten | 1 | 0.2 | 0 | 1 | Bodenfläche | Ku1 | 0 | 0 | NEW | AllplanAttributes - Bezeichnung: PVC Bahnenware Holzoptik; Raumnr. Bauherr: 2.11_A2_02; ash B_Aufbau: B1; ash B_Rutschhemmung: R9
Gipsfaserplatten 2-lagig (BSK) | WUN-H2-E00-073 | CEILING | layer 0.036 m | 1116Dfl0000065965/01 | m² | Trockenbauarbeiten | 1 | 0.036 | 0 | 1 | Deckenfläche |  | 0 | 0 | NEW | 2.5 | AllplanAttributes - Bezeichnung: Gipsfaserplatten 2-lagig (BSK)
Gipsfaserplatten 2-lagig (BSK) | WUN-H2-E00-073 | CEILING | Installationshöhe 0.764 m | 1116Dfl0000065965/02 | m² | Trockenbauarbeiten | 2 | 0.764 | 0 | 1 | Bekleidung | Installationshöhe | 0 | 0 | NEW | 2.5 | Pset_CoveringCommon - FireRating: für korrekte FläVisu; AllplanAttributes - ash_lichte Raumhöhe: 2.500000; OKFF: 0
Gipsfaserplatten 2-lagig (BSK) | WUN-H2-E00-073 | CEILING | A1 0.1 m | 1116Dfl0000065965/03 | m² | Trockenbauarbeiten | 3 | 0.1 | 0 | 1 | Bekleidung | A1 | 0 | 0 | NEW | 2.5 | Pset_CoveringCommon - FireRating: -; AcousticRating: -; AllplanAttributes - ash_lichte Raumhöhe: 2.500000; OKFF: 0
Gipsfaserplatten 2-lagig (BSK) | WUN-H2-E00-073 | CEILING | D1 0.001 m | 1116Dfl0000065965/04 | m² | Maler- und Lackierarbeiten | 4 | 0.001 | 0 | 1 | Bekleidung | D1 | 0 | 0 | NEW | 2.5 | AllplanAttributes - ash_lichte Raumhöhe: 2.500000; OKFF: 0
Gipsfaserplatten 2-lagig (BSK) | WUN-H2-E00-073 | CEILING | layer 0.036 m | 1116Dfl0000065301/01 | m² | Trockenbauarbeiten | 1 | 0.036 | 0 | 1 | Deckenfläche |  | 0 | 0 | NEW | 3.15 | AllplanAttributes - Bezeichnung: Gipsfaserplatten 2-lagig (BSK)
Gipsfaserplatten 2-lagig (BSK) | WUN-H2-E00-073 | CEILING | Installationshöhe 0.114 m | 1116Dfl0000065301/02 | m² | Trockenbauarbeiten | 2 | 0.114 | 0 | 1 | Bekleidung | Installationshöhe | 0 | 0 | NEW | 3.15 | Pset_CoveringCommon - FireRating: -; AcousticRating: -; AllplanAttributes - ash_lichte Raumhöhe: 3.150000
Gipsfaserplatten 2-lagig (BSK) | WUN-H2-E00-073 | CEILING | A1 0.1 m | 1116Dfl0000065301/03 | m² | Trockenbauarbeiten | 3 | 0.1 | 0 | 1 | Bekleidung | A1 | 0 | 0 | NEW | 3.15 | Pset_CoveringCommon - FireRating: -; AcousticRating: -; AllplanAttributes - ash_lichte Raumhöhe: 3.150000
Gipsfaserplatten 2-lagig (BSK) | WUN-H2-E00-073 | CEILING | D1 0.001 m | 1116Dfl0000065301/04 | m² | Maler- und Lackierarbeiten | 4 | 0.001 | 0 | 1 | Bekleidung | D1 | 0 | 0 | NEW | 3.15 | AllplanAttributes - ash_lichte Raumhöhe: 3.150000
Acrobyn | WUN-H2-E00-091 | CLADDING | 84 0.001 m | 1116Sfl0000430204/02 | m² | Maler- und Lackierarbeiten | 2 | 0.001 | 0 | 1 | Seitenfläche | 84 | 0 | 0 | NEW | AllplanAttributes - Bezeichnung: Acrobyn
Acrobyn | WUN-H2-E00-091 | CLADDING | 84 0.001 m | 1116Sfl0000430200/02 | m² | Maler- und Lackierarbeiten | 2 | 0.001 | 0 | 1 | Seitenfläche | 84 | 0 | 0 | NEW | AllplanAttributes - Bezeichnung: Acrobyn
PVC Bahnenware Holzoptik | WUN-H2-E00-091 | FLOORING | Ku1 0.2 m | 1116Bfl0000065310/01 | m² | Bodenbelagsarbeiten | 1 | 0.2 | 0 | 1 | Bodenfläche | Ku1 | 0 | 0 | NEW | AllplanAttributes - Bezeichnung: PVC Bahnenware Holzoptik; Raumnr. Bauherr: 2.11_A2_02; ash B_Aufbau: B1; ash B_Rutschhemmung: R9
Gipsfaserplatten 2-lagig (BSK) | WUN-H2-E00-091 | CEILING | layer 0.036 m | 1116Dfl0000065311/01 | m² | Trockenbauarbeiten | 1 | 0.036 | 0 | 1 | Deckenfläche |  | 0 | 0 | NEW | 3.15 | AllplanAttributes - Bezeichnung: Gipsfaserplatten 2-lagig (BSK)
Gipsfaserplatten 2-lagig (BSK) | WUN-H2-E00-091 | CEILING | Installationshöhe 0.114 m | 1116Dfl0000065311/02 | m² | Trockenbauarbeiten | 2 | 0.114 | 0 | 1 | Bekleidung | Installationshöhe | 0 | 0 | NEW | 3.15 | Pset_CoveringCommon - FireRating: -; AcousticRating: -; AllplanAttributes - ash_lichte Raumhöhe: 3.150000
Gipsfaserplatten 2-lagig (BSK) | WUN-H2-E00-091 | CEILING | A1 0.1 m | 1116Dfl0000065311/03 | m² | Trockenbauarbeiten | 3 | 0.1 | 0 | 1 | Bekleidung | A1 | 0 | 0 | NEW | 3.15 | Pset_CoveringCommon - FireRating: -; AcousticRating: -; AllplanAttributes - ash_lichte Raumhöhe: 3.150000
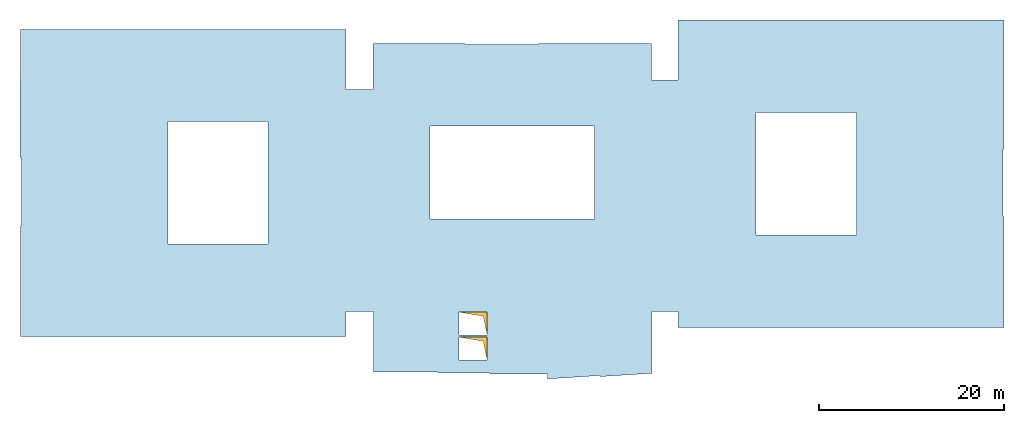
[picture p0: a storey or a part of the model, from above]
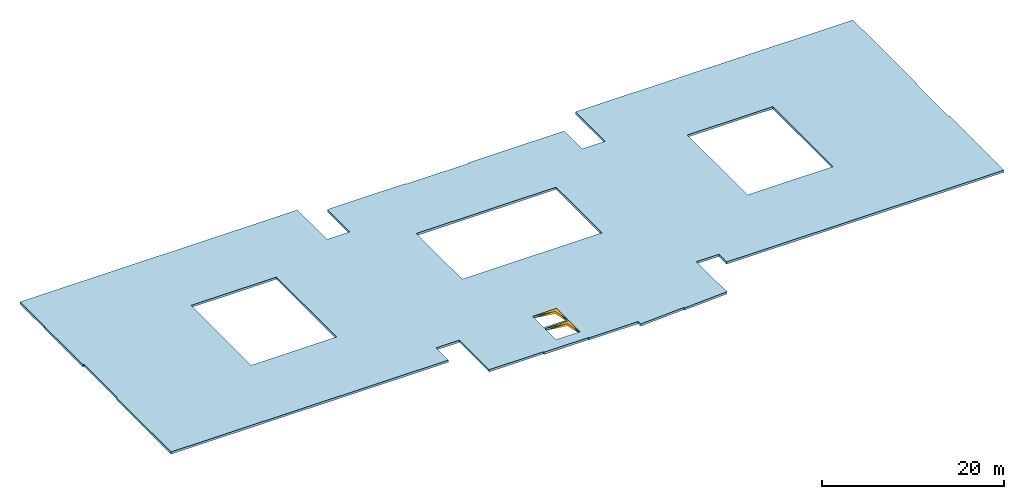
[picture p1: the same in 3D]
Properties of the parts of a building model (IFC4), part 22 of 80

# IfcCovering (3945)
Name | In | PredefinedType | Material | Allright_Bauteil_ID | Abrechnungsart | Gewerk | Schichtnummer | Schichtdicke (m) | Dicke (m) | Faktor | Objektname | AllplanAttributes, Material | Bezugshöhe | Deltahöhe | Status | D_lichte Raumhöhe [Zahl] (m)
Gipsfaserplatten 2-lagig (BSK) | WUN-H2-E00-091 | CEILING | D1 0.001 m | 1116Dfl0000065311/04 | m² | Maler- und Lackierarbeiten | 4 | 0.001 | 0 | 1 | Bekleidung | D1 | 0 | 0 | NEW | 3.15 | AllplanAttributes - ash_lichte Raumhöhe: 3.150000
Gipsfaserplatten 2-lagig (BSK) | WUN-H2-E00-091 | CEILING | layer 0.036 m | 1116Dfl0000065959/01 | m² | Trockenbauarbeiten | 1 | 0.036 | 0 | 1 | Deckenfläche |  | 0 | 0 | NEW | 2.5 | AllplanAttributes - Bezeichnung: Gipsfaserplatten 2-lagig (BSK)
Gipsfaserplatten 2-lagig (BSK) | WUN-H2-E00-091 | CEILING | Installationshöhe 0.764 m | 1116Dfl0000065959/02 | m² | Trockenbauarbeiten | 2 | 0.764 | 0 | 1 | Bekleidung | Installationshöhe | 0 | 0 | NEW | 2.5 | Pset_CoveringCommon - FireRating: für korrekte FläVisu; AllplanAttributes - ash_lichte Raumhöhe: 2.500000; OKFF: 0
Gipsfaserplatten 2-lagig (BSK) | WUN-H2-E00-091 | CEILING | A1 0.1 m | 1116Dfl0000065959/03 | m² | Trockenbauarbeiten | 3 | 0.1 | 0 | 1 | Bekleidung | A1 | 0 | 0 | NEW | 2.5 | Pset_CoveringCommon - FireRating: -; AcousticRating: -; AllplanAttributes - ash_lichte Raumhöhe: 2.500000; OKFF: 0
Gipsfaserplatten 2-lagig (BSK) | WUN-H2-E00-091 | CEILING | D1 0.001 m | 1116Dfl0000065959/04 | m² | Maler- und Lackierarbeiten | 4 | 0.001 | 0 | 1 | Bekleidung | D1 | 0 | 0 | NEW | 2.5 | AllplanAttributes - ash_lichte Raumhöhe: 2.500000; OKFF: 0
Acrobyn | WUN-H2-E00-092 | CLADDING | 84 0.001 m | 1116Sfl0000430199/02 | m² | Maler- und Lackierarbeiten | 2 | 0.001 | 0 | 1 | Seitenfläche | 84 | 0 | 0 | NEW | AllplanAttributes - Bezeichnung: Acrobyn
Acrobyn | WUN-H2-E00-092 | CLADDING | 84 0.001 m | 1116Sfl0000430197/02 | m² | Maler- und Lackierarbeiten | 2 | 0.001 | 0 | 1 | Seitenfläche | 84 | 0 | 0 | NEW | AllplanAttributes - Bezeichnung: Acrobyn
PVC Bahnenware Holzoptik | WUN-H2-E00-092 | FLOORING | Ku1 0.2 m | 1116Bfl0000065306/01 | m² | Bodenbelagsarbeiten | 1 | 0.2 | 0 | 1 | Bodenfläche | Ku1 | 0 | 0 | NEW | AllplanAttributes - Bezeichnung: PVC Bahnenware Holzoptik; Raumnr. Bauherr: 2.11_A2_02; ash B_Aufbau: B1; ash B_Rutschhemmung: R9
Gipsfaserplatten 2-lagig (BSK) | WUN-H2-E00-092 | CEILING | layer 0.036 m | 1116Dfl0000065307/01 | m² | Trockenbauarbeiten | 1 | 0.036 | 0 | 1 | Deckenfläche |  | 0 | 0 | NEW | 3.15 | AllplanAttributes - Bezeichnung: Gipsfaserplatten 2-lagig (BSK)
Gipsfaserplatten 2-lagig (BSK) | WUN-H2-E00-092 | CEILING | Installationshöhe 0.114 m | 1116Dfl0000065307/02 | m² | Trockenbauarbeiten | 2 | 0.114 | 0 | 1 | Bekleidung | Installationshöhe | 0 | 0 | NEW | 3.15 | Pset_CoveringCommon - FireRating: -; AcousticRating: -; AllplanAttributes - ash_lichte Raumhöhe: 3.150000
Gipsfaserplatten 2-lagig (BSK) | WUN-H2-E00-092 | CEILING | A1 0.1 m | 1116Dfl0000065307/03 | m² | Trockenbauarbeiten | 3 | 0.1 | 0 | 1 | Bekleidung | A1 | 0 | 0 | NEW | 3.15 | Pset_CoveringCommon - FireRating: -; AcousticRating: -; AllplanAttributes - ash_lichte Raumhöhe: 3.150000
Gipsfaserplatten 2-lagig (BSK) | WUN-H2-E00-092 | CEILING | D1 0.001 m | 1116Dfl0000065307/04 | m² | Maler- und Lackierarbeiten | 4 | 0.001 | 0 | 1 | Bekleidung | D1 | 0 | 0 | NEW | 3.15 | AllplanAttributes - ash_lichte Raumhöhe: 3.150000
Gipsfaserplatten 2-lagig (BSK) | WUN-H2-E00-092 | CEILING | layer 0.036 m | 1116Dfl0000065957/01 | m² | Trockenbauarbeiten | 1 | 0.036 | 0 | 1 | Deckenfläche |  | 0 | 0 | NEW | 2.5 | AllplanAttributes - Bezeichnung: Gipsfaserplatten 2-lagig (BSK)
Gipsfaserplatten 2-lagig (BSK) | WUN-H2-E00-092 | CEILING | Installationshöhe 0.764 m | 1116Dfl0000065957/02 | m² | Trockenbauarbeiten | 2 | 0.764 | 0 | 1 | Bekleidung | Installationshöhe | 0 | 0 | NEW | 2.5 | Pset_CoveringCommon - FireRating: für korrekte FläVisu; AllplanAttributes - ash_lichte Raumhöhe: 2.500000; OKFF: 0
Gipsfaserplatten 2-lagig (BSK) | WUN-H2-E00-092 | CEILING | A1 0.1 m | 1116Dfl0000065957/03 | m² | Trockenbauarbeiten | 3 | 0.1 | 0 | 1 | Bekleidung | A1 | 0 | 0 | NEW | 2.5 | Pset_CoveringCommon - FireRating: -; AcousticRating: -; AllplanAttributes - ash_lichte Raumhöhe: 2.500000; OKFF: 0
Gipsfaserplatten 2-lagig (BSK) | WUN-H2-E00-092 | CEILING | D1 0.001 m | 1116Dfl0000065957/04 | m² | Maler- und Lackierarbeiten | 4 | 0.001 | 0 | 1 | Bekleidung | D1 | 0 | 0 | NEW | 2.5 | AllplanAttributes - ash_lichte Raumhöhe: 2.500000; OKFF: 0
Acrobyn | WUN-H2-E00-095 | CLADDING | 84 0.001 m | 1116Sfl0000430188/02 | m² | Maler- und Lackierarbeiten | 2 | 0.001 | 0 | 1 | Seitenfläche | 84 | 0 | 0 | NEW | AllplanAttributes - Bezeichnung: Acrobyn
Acrobyn | WUN-H2-E00-095 | CLADDING | 84 0.001 m | 1116Sfl0000430183/02 | m² | Maler- und Lackierarbeiten | 2 | 0.001 | 0 | 1 | Seitenfläche | 84 | 0 | 0 | NEW | AllplanAttributes - Bezeichnung: Acrobyn
PVC Bahnenware Holzoptik | WUN-H2-E00-095 | FLOORING | Ku1 0.2 m | 1116Bfl0000065312/01 | m² | Bodenbelagsarbeiten | 1 | 0.2 | 0 | 1 | Bodenfläche | Ku1 | 0 | 0 | NEW | AllplanAttributes - Bezeichnung: PVC Bahnenware Holzoptik; Raumnr. Bauherr: 2.11_A2_02; ash B_Aufbau: B1; ash B_Rutschhemmung: R9
Gipsfaserplatten 2-lagig (BSK) | WUN-H2-E00-095 | CEILING | layer 0.036 m | 1116Dfl0000065951/01 | m² | Trockenbauarbeiten | 1 | 0.036 | 0 | 1 | Deckenfläche |  | 0 | 0 | NEW | 2.5 | AllplanAttributes - Bezeichnung: Gipsfaserplatten 2-lagig (BSK)
Gipsfaserplatten 2-lagig (BSK) | WUN-H2-E00-095 | CEILING | Installationshöhe 0.764 m | 1116Dfl0000065951/02 | m² | Trockenbauarbeiten | 2 | 0.764 | 0 | 1 | Bekleidung | Installationshöhe | 0 | 0 | NEW | 2.5 | Pset_CoveringCommon - FireRating: für korrekte FläVisu; AllplanAttributes - ash_lichte Raumhöhe: 2.500000; OKFF: 0
Gipsfaserplatten 2-lagig (BSK) | WUN-H2-E00-095 | CEILING | A1 0.1 m | 1116Dfl0000065951/03 | m² | Trockenbauarbeiten | 3 | 0.1 | 0 | 1 | Bekleidung | A1 | 0 | 0 | NEW | 2.5 | Pset_CoveringCommon - FireRating: -; AcousticRating: -; AllplanAttributes - ash_lichte Raumhöhe: 2.500000; OKFF: 0
Gipsfaserplatten 2-lagig (BSK) | WUN-H2-E00-095 | CEILING | D1 0.001 m | 1116Dfl0000065951/04 | m² | Maler- und Lackierarbeiten | 4 | 0.001 | 0 | 1 | Bekleidung | D1 | 0 | 0 | NEW | 2.5 | AllplanAttributes - ash_lichte Raumhöhe: 2.500000; OKFF: 0
Gipsfaserplatten 2-lagig (BSK) | WUN-H2-E00-095 | CEILING | layer 0.036 m | 1116Dfl0000065313/01 | m² | Trockenbauarbeiten | 1 | 0.036 | 0 | 1 | Deckenfläche |  | 0 | 0 | NEW | 3.15 | AllplanAttributes - Bezeichnung: Gipsfaserplatten 2-lagig (BSK)
Gipsfaserplatten 2-lagig (BSK) | WUN-H2-E00-095 | CEILING | Installationshöhe 0.114 m | 1116Dfl0000065313/02 | m² | Trockenbauarbeiten | 2 | 0.114 | 0 | 1 | Bekleidung | Installationshöhe | 0 | 0 | NEW | 3.15 | Pset_CoveringCommon - FireRating: -; AcousticRating: -; AllplanAttributes - ash_lichte Raumhöhe: 3.150000
Gipsfaserplatten 2-lagig (BSK) | WUN-H2-E00-095 | CEILING | A1 0.1 m | 1116Dfl0000065313/03 | m² | Trockenbauarbeiten | 3 | 0.1 | 0 | 1 | Bekleidung | A1 | 0 | 0 | NEW | 3.15 | Pset_CoveringCommon - FireRating: -; AcousticRating: -; AllplanAttributes - ash_lichte Raumhöhe: 3.150000
Gipsfaserplatten 2-lagig (BSK) | WUN-H2-E00-095 | CEILING | D1 0.001 m | 1116Dfl0000065313/04 | m² | Maler- und Lackierarbeiten | 4 | 0.001 | 0 | 1 | Bekleidung | D1 | 0 | 0 | NEW | 3.15 | AllplanAttributes - ash_lichte Raumhöhe: 3.150000
Acrobyn | WUN-H2-E00-025 | CLADDING | 84 0.001 m | 1116Sfl0000430225/02 | m² | Maler- und Lackierarbeiten | 2 | 0.001 | 0 | 1 | Seitenfläche | 84 | 0 | 0 | NEW | AllplanAttributes - Bezeichnung: Acrobyn
Acrobyn | WUN-H2-E00-025 | CLADDING | 84 0.001 m | 1116Sfl0000430237/02 | m² | Maler- und Lackierarbeiten | 2 | 0.001 | 0 | 1 | Seitenfläche | 84 | 0 | 0 | NEW | AllplanAttributes - Bezeichnung: Acrobyn
PVC Bahnenware Holzoptik | WUN-H2-E00-025 | FLOORING | Ku1 0.2 m | 1116Bfl0000065284/01 | m² | Bodenbelagsarbeiten | 1 | 0.2 | 0 | 1 | Bodenfläche | Ku1 | 0 | 0 | NEW | AllplanAttributes - Bezeichnung: PVC Bahnenware Holzoptik; Raumnr. Bauherr: 2.11_A2_02; ash B_Aufbau: B1; ash B_Rutschhemmung: R9
Gipsfaserplatten 2-lagig (BSK) | WUN-H2-E00-025 | CEILING | layer 0.036 m | 1116Dfl0000065945/01 | m² | Trockenbauarbeiten | 1 | 0.036 | 0 | 1 | Deckenfläche |  | 0 | 0 | NEW | 2.5 | AllplanAttributes - Bezeichnung: Gipsfaserplatten 2-lagig (BSK)
Gipsfaserplatten 2-lagig (BSK) | WUN-H2-E00-025 | CEILING | Installationshöhe 0.764 m | 1116Dfl0000065945/02 | m² | Trockenbauarbeiten | 2 | 0.764 | 0 | 1 | Bekleidung | Installationshöhe | 0 | 0 | NEW | 2.5 | Pset_CoveringCommon - FireRating: für korrekte FläVisu; AllplanAttributes - ash_lichte Raumhöhe: 2.500000; OKFF: 0
Gipsfaserplatten 2-lagig (BSK) | WUN-H2-E00-025 | CEILING | A1 0.1 m | 1116Dfl0000065945/03 | m² | Trockenbauarbeiten | 3 | 0.1 | 0 | 1 | Bekleidung | A1 | 0 | 0 | NEW | 2.5 | Pset_CoveringCommon - FireRating: -; AcousticRating: -; AllplanAttributes - ash_lichte Raumhöhe: 2.500000; OKFF: 0
Gipsfaserplatten 2-lagig (BSK) | WUN-H2-E00-025 | CEILING | D1 0.001 m | 1116Dfl0000065945/04 | m² | Maler- und Lackierarbeiten | 4 | 0.001 | 0 | 1 | Bekleidung | D1 | 0 | 0 | NEW | 2.5 | AllplanAttributes - ash_lichte Raumhöhe: 2.500000; OKFF: 0
Gipsfaserplatten 2-lagig (BSK) | WUN-H2-E00-025 | CEILING | layer 0.036 m | 1116Dfl0000065285/01 | m² | Trockenbauarbeiten | 1 | 0.036 | 0 | 1 | Deckenfläche |  | 0 | 0 | NEW | 3.15 | AllplanAttributes - Bezeichnung: Gipsfaserplatten 2-lagig (BSK)
Gipsfaserplatten 2-lagig (BSK) | WUN-H2-E00-025 | CEILING | Installationshöhe 0.114 m | 1116Dfl0000065285/02 | m² | Trockenbauarbeiten | 2 | 0.114 | 0 | 1 | Bekleidung | Installationshöhe | 0 | 0 | NEW | 3.15 | Pset_CoveringCommon - FireRating: -; AcousticRating: -; AllplanAttributes - ash_lichte Raumhöhe: 3.150000
Gipsfaserplatten 2-lagig (BSK) | WUN-H2-E00-025 | CEILING | A1 0.1 m | 1116Dfl0000065285/03 | m² | Trockenbauarbeiten | 3 | 0.1 | 0 | 1 | Bekleidung | A1 | 0 | 0 | NEW | 3.15 | Pset_CoveringCommon - FireRating: -; AcousticRating: -; AllplanAttributes - ash_lichte Raumhöhe: 3.150000
Gipsfaserplatten 2-lagig (BSK) | WUN-H2-E00-025 | CEILING | D1 0.001 m | 1116Dfl0000065285/04 | m² | Maler- und Lackierarbeiten | 4 | 0.001 | 0 | 1 | Bekleidung | D1 | 0 | 0 | NEW | 3.15 | AllplanAttributes - ash_lichte Raumhöhe: 3.150000
Acrobyn | WUN-H2-E00-024 | CLADDING | 84 0.001 m | 1116Sfl0000430223/02 | m² | Maler- und Lackierarbeiten | 2 | 0.001 | 0 | 1 | Seitenfläche | 84 | 0 | 0 | NEW | AllplanAttributes - Bezeichnung: Acrobyn
Acrobyn | WUN-H2-E00-024 | CLADDING | 84 0.001 m | 1116Sfl0000430235/02 | m² | Maler- und Lackierarbeiten | 2 | 0.001 | 0 | 1 | Seitenfläche | 84 | 0 | 0 | NEW | AllplanAttributes - Bezeichnung: Acrobyn
PVC Bahnenware Holzoptik | WUN-H2-E00-024 | FLOORING | Ku1 0.2 m | 1116Bfl0000065286/01 | m² | Bodenbelagsarbeiten | 1 | 0.2 | 0 | 1 | Bodenfläche | Ku1 | 0 | 0 | NEW | AllplanAttributes - Bezeichnung: PVC Bahnenware Holzoptik; Raumnr. Bauherr: 2.11_A2_02; ash B_Aufbau: B1; ash B_Rutschhemmung: R9
Gipsfaserplatten 2-lagig (BSK) | WUN-H2-E00-024 | CEILING | layer 0.036 m | 1116Dfl0000065943/01 | m² | Trockenbauarbeiten | 1 | 0.036 | 0 | 1 | Deckenfläche |  | 0 | 0 | NEW | 2.5 | AllplanAttributes - Bezeichnung: Gipsfaserplatten 2-lagig (BSK)
Gipsfaserplatten 2-lagig (BSK) | WUN-H2-E00-024 | CEILING | Installationshöhe 0.764 m | 1116Dfl0000065943/02 | m² | Trockenbauarbeiten | 2 | 0.764 | 0 | 1 | Bekleidung | Installationshöhe | 0 | 0 | NEW | 2.5 | Pset_CoveringCommon - FireRating: für korrekte FläVisu; AllplanAttributes - ash_lichte Raumhöhe: 2.500000; OKFF: 0
Gipsfaserplatten 2-lagig (BSK) | WUN-H2-E00-024 | CEILING | A1 0.1 m | 1116Dfl0000065943/03 | m² | Trockenbauarbeiten | 3 | 0.1 | 0 | 1 | Bekleidung | A1 | 0 | 0 | NEW | 2.5 | Pset_CoveringCommon - FireRating: -; AcousticRating: -; AllplanAttributes - ash_lichte Raumhöhe: 2.500000; OKFF: 0
Gipsfaserplatten 2-lagig (BSK) | WUN-H2-E00-024 | CEILING | D1 0.001 m | 1116Dfl0000065943/04 | m² | Maler- und Lackierarbeiten | 4 | 0.001 | 0 | 1 | Bekleidung | D1 | 0 | 0 | NEW | 2.5 | AllplanAttributes - ash_lichte Raumhöhe: 2.500000; OKFF: 0
Gipsfaserplatten 2-lagig (BSK) | WUN-H2-E00-024 | CEILING | layer 0.036 m | 1116Dfl0000065287/01 | m² | Trockenbauarbeiten | 1 | 0.036 | 0 | 1 | Deckenfläche |  | 0 | 0 | NEW | 3.15 | AllplanAttributes - Bezeichnung: Gipsfaserplatten 2-lagig (BSK)
Gipsfaserplatten 2-lagig (BSK) | WUN-H2-E00-024 | CEILING | Installationshöhe 0.114 m | 1116Dfl0000065287/02 | m² | Trockenbauarbeiten | 2 | 0.114 | 0 | 1 | Bekleidung | Installationshöhe | 0 | 0 | NEW | 3.15 | Pset_CoveringCommon - FireRating: -; AcousticRating: -; AllplanAttributes - ash_lichte Raumhöhe: 3.150000
Gipsfaserplatten 2-lagig (BSK) | WUN-H2-E00-024 | CEILING | A1 0.1 m | 1116Dfl0000065287/03 | m² | Trockenbauarbeiten | 3 | 0.1 | 0 | 1 | Bekleidung | A1 | 0 | 0 | NEW | 3.15 | Pset_CoveringCommon - FireRating: -; AcousticRating: -; AllplanAttributes - ash_lichte Raumhöhe: 3.150000
Gipsfaserplatten 2-lagig (BSK) | WUN-H2-E00-024 | CEILING | D1 0.001 m | 1116Dfl0000065287/04 | m² | Maler- und Lackierarbeiten | 4 | 0.001 | 0 | 1 | Bekleidung | D1 | 0 | 0 | NEW | 3.15 | AllplanAttributes - ash_lichte Raumhöhe: 3.150000
Acrobyn | WUN-H2-E00-022 | CLADDING | 84 0.001 m | 1116Sfl0000430219/02 | m² | Maler- und Lackierarbeiten | 2 | 0.001 | 0 | 1 | Seitenfläche | 84 | 0 | 0 | NEW | AllplanAttributes - Bezeichnung: Acrobyn
PVC Bahnenware Holzoptik | WUN-H2-E00-022 | FLOORING | Ku1 0.2 m | 1116Bfl0000065276/01 | m² | Bodenbelagsarbeiten | 1 | 0.2 | 0 | 1 | Bodenfläche | Ku1 | 0 | 0 | NEW | AllplanAttributes - Bezeichnung: PVC Bahnenware Holzoptik; Raumnr. Bauherr: 2.11_A2_02; ash B_Aufbau: B1; ash B_Rutschhemmung: R9
Gipsfaserplatten 2-lagig (BSK) | WUN-H2-E00-022 | CEILING | layer 0.036 m | 1116Dfl0000065937/01 | m² | Trockenbauarbeiten | 1 | 0.036 | 0 | 1 | Deckenfläche |  | 0 | 0 | NEW | 2.5 | AllplanAttributes - Bezeichnung: Gipsfaserplatten 2-lagig (BSK)
Gipsfaserplatten 2-lagig (BSK) | WUN-H2-E00-022 | CEILING | Installationshöhe 0.764 m | 1116Dfl0000065937/02 | m² | Trockenbauarbeiten | 2 | 0.764 | 0 | 1 | Bekleidung | Installationshöhe | 0 | 0 | NEW | 2.5 | Pset_CoveringCommon - FireRating: für korrekte FläVisu; AllplanAttributes - ash_lichte Raumhöhe: 2.500000; OKFF: 0
Gipsfaserplatten 2-lagig (BSK) | WUN-H2-E00-022 | CEILING | A1 0.1 m | 1116Dfl0000065937/03 | m² | Trockenbauarbeiten | 3 | 0.1 | 0 | 1 | Bekleidung | A1 | 0 | 0 | NEW | 2.5 | Pset_CoveringCommon - FireRating: -; AcousticRating: -; AllplanAttributes - ash_lichte Raumhöhe: 2.500000; OKFF: 0
Gipsfaserplatten 2-lagig (BSK) | WUN-H2-E00-022 | CEILING | D1 0.001 m | 1116Dfl0000065937/04 | m² | Maler- und Lackierarbeiten | 4 | 0.001 | 0 | 1 | Bekleidung | D1 | 0 | 0 | NEW | 2.5 | AllplanAttributes - ash_lichte Raumhöhe: 2.500000; OKFF: 0
Gipsfaserplatten 2-lagig (BSK) | WUN-H2-E00-022 | CEILING | layer 0.036 m | 1116Dfl0000065277/01 | m² | Trockenbauarbeiten | 1 | 0.036 | 0 | 1 | Deckenfläche |  | 0 | 0 | NEW | 3.15 | AllplanAttributes - Bezeichnung: Gipsfaserplatten 2-lagig (BSK)
Gipsfaserplatten 2-lagig (BSK) | WUN-H2-E00-022 | CEILING | Installationshöhe 0.114 m | 1116Dfl0000065277/02 | m² | Trockenbauarbeiten | 2 | 0.114 | 0 | 1 | Bekleidung | Installationshöhe | 0 | 0 | NEW | 3.15 | Pset_CoveringCommon - FireRating: -; AcousticRating: -; AllplanAttributes - ash_lichte Raumhöhe: 3.150000
Gipsfaserplatten 2-lagig (BSK) | WUN-H2-E00-022 | CEILING | A1 0.1 m | 1116Dfl0000065277/03 | m² | Trockenbauarbeiten | 3 | 0.1 | 0 | 1 | Bekleidung | A1 | 0 | 0 | NEW | 3.15 | Pset_CoveringCommon - FireRating: -; AcousticRating: -; AllplanAttributes - ash_lichte Raumhöhe: 3.150000
Gipsfaserplatten 2-lagig (BSK) | WUN-H2-E00-022 | CEILING | D1 0.001 m | 1116Dfl0000065277/04 | m² | Maler- und Lackierarbeiten | 4 | 0.001 | 0 | 1 | Bekleidung | D1 | 0 | 0 | NEW | 3.15 | AllplanAttributes - ash_lichte Raumhöhe: 3.150000
Acrobyn | WUN-H2-E00-021 | CLADDING | 84 0.001 m | 1116Sfl0000430217/02 | m² | Maler- und Lackierarbeiten | 2 | 0.001 | 0 | 1 | Seitenfläche | 84 | 0 | 0 | NEW | AllplanAttributes - Bezeichnung: Acrobyn
Acrobyn | WUN-H2-E00-021 | CLADDING | 84 0.001 m | 1116Sfl0000430231/02 | m² | Maler- und Lackierarbeiten | 2 | 0.001 | 0 | 1 | Seitenfläche | 84 | 0 | 0 | NEW | AllplanAttributes - Bezeichnung: Acrobyn
PVC Bahnenware Holzoptik | WUN-H2-E00-021 | FLOORING | Ku1 0.2 m | 1116Bfl0000065280/01 | m² | Bodenbelagsarbeiten | 1 | 0.2 | 0 | 1 | Bodenfläche | Ku1 | 0 | 0 | NEW | AllplanAttributes - Bezeichnung: PVC Bahnenware Holzoptik; Raumnr. Bauherr: 2.11_A2_02; ash B_Aufbau: B1; ash B_Rutschhemmung: R9
Gipsfaserplatten 2-lagig (BSK) | WUN-H2-E00-021 | CEILING | layer 0.036 m | 1116Dfl0000065941/01 | m² | Trockenbauarbeiten | 1 | 0.036 | 0 | 1 | Deckenfläche |  | 0 | 0 | NEW | 2.5 | AllplanAttributes - Bezeichnung: Gipsfaserplatten 2-lagig (BSK)
Gipsfaserplatten 2-lagig (BSK) | WUN-H2-E00-021 | CEILING | Installationshöhe 0.764 m | 1116Dfl0000065941/02 | m² | Trockenbauarbeiten | 2 | 0.764 | 0 | 1 | Bekleidung | Installationshöhe | 0 | 0 | NEW | 2.5 | Pset_CoveringCommon - FireRating: für korrekte FläVisu; AllplanAttributes - ash_lichte Raumhöhe: 2.500000; OKFF: 0
Gipsfaserplatten 2-lagig (BSK) | WUN-H2-E00-021 | CEILING | A1 0.1 m | 1116Dfl0000065941/03 | m² | Trockenbauarbeiten | 3 | 0.1 | 0 | 1 | Bekleidung | A1 | 0 | 0 | NEW | 2.5 | Pset_CoveringCommon - FireRating: -; AcousticRating: -; AllplanAttributes - ash_lichte Raumhöhe: 2.500000; OKFF: 0
Gipsfaserplatten 2-lagig (BSK) | WUN-H2-E00-021 | CEILING | D1 0.001 m | 1116Dfl0000065941/04 | m² | Maler- und Lackierarbeiten | 4 | 0.001 | 0 | 1 | Bekleidung | D1 | 0 | 0 | NEW | 2.5 | AllplanAttributes - ash_lichte Raumhöhe: 2.500000; OKFF: 0
Gipsfaserplatten 2-lagig (BSK) | WUN-H2-E00-021 | CEILING | layer 0.036 m | 1116Dfl0000065281/01 | m² | Trockenbauarbeiten | 1 | 0.036 | 0 | 1 | Deckenfläche |  | 0 | 0 | NEW | 3.15 | AllplanAttributes - Bezeichnung: Gipsfaserplatten 2-lagig (BSK)
Gipsfaserplatten 2-lagig (BSK) | WUN-H2-E00-021 | CEILING | Installationshöhe 0.114 m | 1116Dfl0000065281/02 | m² | Trockenbauarbeiten | 2 | 0.114 | 0 | 1 | Bekleidung | Installationshöhe | 0 | 0 | NEW | 3.15 | Pset_CoveringCommon - FireRating: -; AcousticRating: -; AllplanAttributes - ash_lichte Raumhöhe: 3.150000
Gipsfaserplatten 2-lagig (BSK) | WUN-H2-E00-021 | CEILING | A1 0.1 m | 1116Dfl0000065281/03 | m² | Trockenbauarbeiten | 3 | 0.1 | 0 | 1 | Bekleidung | A1 | 0 | 0 | NEW | 3.15 | Pset_CoveringCommon - FireRating: -; AcousticRating: -; AllplanAttributes - ash_lichte Raumhöhe: 3.150000
Gipsfaserplatten 2-lagig (BSK) | WUN-H2-E00-021 | CEILING | D1 0.001 m | 1116Dfl0000065281/04 | m² | Maler- und Lackierarbeiten | 4 | 0.001 | 0 | 1 | Bekleidung | D1 | 0 | 0 | NEW | 3.15 | AllplanAttributes - ash_lichte Raumhöhe: 3.150000
Acrobyn | WUN-H2-E00-020 | CLADDING | 84 0.001 m | 1116Sfl0000430215/02 | m² | Maler- und Lackierarbeiten | 2 | 0.001 | 0 | 1 | Seitenfläche | 84 | 0 | 0 | NEW | AllplanAttributes - Bezeichnung: Acrobyn
Acrobyn | WUN-H2-E00-020 | CLADDING | 84 0.001 m | 1116Sfl0000430229/02 | m² | Maler- und Lackierarbeiten | 2 | 0.001 | 0 | 1 | Seitenfläche | 84 | 0 | 0 | NEW | AllplanAttributes - Bezeichnung: Acrobyn
PVC Bahnenware Holzoptik | WUN-H2-E00-020 | FLOORING | Ku1 0.2 m | 1116Bfl0000065282/01 | m² | Bodenbelagsarbeiten | 1 | 0.2 | 0 | 1 | Bodenfläche | Ku1 | 0 | 0 | NEW | AllplanAttributes - Bezeichnung: PVC Bahnenware Holzoptik; Raumnr. Bauherr: 2.11_A2_02; ash B_Aufbau: B1; ash B_Rutschhemmung: R9
Gipsfaserplatten 2-lagig (BSK) | WUN-H2-E00-020 | CEILING | layer 0.036 m | 1116Dfl0000065939/01 | m² | Trockenbauarbeiten | 1 | 0.036 | 0 | 1 | Deckenfläche |  | 0 | 0 | NEW | 2.5 | AllplanAttributes - Bezeichnung: Gipsfaserplatten 2-lagig (BSK)
Gipsfaserplatten 2-lagig (BSK) | WUN-H2-E00-020 | CEILING | Installationshöhe 0.764 m | 1116Dfl0000065939/02 | m² | Trockenbauarbeiten | 2 | 0.764 | 0 | 1 | Bekleidung | Installationshöhe | 0 | 0 | NEW | 2.5 | Pset_CoveringCommon - FireRating: für korrekte FläVisu; AllplanAttributes - ash_lichte Raumhöhe: 2.500000; OKFF: 0
Gipsfaserplatten 2-lagig (BSK) | WUN-H2-E00-020 | CEILING | A1 0.1 m | 1116Dfl0000065939/03 | m² | Trockenbauarbeiten | 3 | 0.1 | 0 | 1 | Bekleidung | A1 | 0 | 0 | NEW | 2.5 | Pset_CoveringCommon - FireRating: -; AcousticRating: -; AllplanAttributes - ash_lichte Raumhöhe: 2.500000; OKFF: 0
Gipsfaserplatten 2-lagig (BSK) | WUN-H2-E00-020 | CEILING | D1 0.001 m | 1116Dfl0000065939/04 | m² | Maler- und Lackierarbeiten | 4 | 0.001 | 0 | 1 | Bekleidung | D1 | 0 | 0 | NEW | 2.5 | AllplanAttributes - ash_lichte Raumhöhe: 2.500000; OKFF: 0
Gipsfaserplatten 2-lagig (BSK) | WUN-H2-E00-020 | CEILING | layer 0.036 m | 1116Dfl0000065283/01 | m² | Trockenbauarbeiten | 1 | 0.036 | 0 | 1 | Deckenfläche |  | 0 | 0 | NEW | 3.15 | AllplanAttributes - Bezeichnung: Gipsfaserplatten 2-lagig (BSK)
Gipsfaserplatten 2-lagig (BSK) | WUN-H2-E00-020 | CEILING | Installationshöhe 0.114 m | 1116Dfl0000065283/02 | m² | Trockenbauarbeiten | 2 | 0.114 | 0 | 1 | Bekleidung | Installationshöhe | 0 | 0 | NEW | 3.15 | Pset_CoveringCommon - FireRating: -; AcousticRating: -; AllplanAttributes - ash_lichte Raumhöhe: 3.150000
Gipsfaserplatten 2-lagig (BSK) | WUN-H2-E00-020 | CEILING | A1 0.1 m | 1116Dfl0000065283/03 | m² | Trockenbauarbeiten | 3 | 0.1 | 0 | 1 | Bekleidung | A1 | 0 | 0 | NEW | 3.15 | Pset_CoveringCommon - FireRating: -; AcousticRating: -; AllplanAttributes - ash_lichte Raumhöhe: 3.150000
Gipsfaserplatten 2-lagig (BSK) | WUN-H2-E00-020 | CEILING | D1 0.001 m | 1116Dfl0000065283/04 | m² | Maler- und Lackierarbeiten | 4 | 0.001 | 0 | 1 | Bekleidung | D1 | 0 | 0 | NEW | 3.15 | AllplanAttributes - ash_lichte Raumhöhe: 3.150000
Acrobyn | WUN-H2-E00-019 | CLADDING | 84 0.001 m | 1116Sfl0000430213/02 | m² | Maler- und Lackierarbeiten | 2 | 0.001 | 0 | 1 | Seitenfläche | 84 | 0 | 0 | NEW | AllplanAttributes - Bezeichnung: Acrobyn
Acrobyn | WUN-H2-E00-019 | CLADDING | 84 0.001 m | 1116Sfl0000430227/02 | m² | Maler- und Lackierarbeiten | 2 | 0.001 | 0 | 1 | Seitenfläche | 84 | 0 | 0 | NEW | AllplanAttributes - Bezeichnung: Acrobyn
PVC Bahnenware Holzoptik | WUN-H2-E00-019 | FLOORING | Ku1 0.2 m | 1116Bfl0000066558/01 | m² | Bodenbelagsarbeiten | 1 | 0.2 | 0 | 1 | Bodenfläche | Ku1 | 0 | 0 | NEW | AllplanAttributes - Bezeichnung: PVC Bahnenware Holzoptik; Raumnr. Bauherr: 2.11_A2_02; ash B_Aufbau: B1; ash B_Rutschhemmung: R9
Gipsfaserplatten 2-lagig (BSK) | WUN-H2-E00-019 | CEILING | layer 0.036 m | 1116Dfl0000066562/01 | m² | Trockenbauarbeiten | 1 | 0.036 | 0 | 1 | Deckenfläche |  | 0 | 0 | NEW | 2.5 | AllplanAttributes - Bezeichnung: Gipsfaserplatten 2-lagig (BSK)
Gipsfaserplatten 2-lagig (BSK) | WUN-H2-E00-019 | CEILING | Installationshöhe 0.764 m | 1116Dfl0000066562/02 | m² | Trockenbauarbeiten | 2 | 0.764 | 0 | 1 | Bekleidung | Installationshöhe | 0 | 0 | NEW | 2.5 | Pset_CoveringCommon - FireRating: für korrekte FläVisu; AllplanAttributes - ash_lichte Raumhöhe: 2.500000; OKFF: 0
Gipsfaserplatten 2-lagig (BSK) | WUN-H2-E00-019 | CEILING | A1 0.1 m | 1116Dfl0000066562/03 | m² | Trockenbauarbeiten | 3 | 0.1 | 0 | 1 | Bekleidung | A1 | 0 | 0 | NEW | 2.5 | Pset_CoveringCommon - FireRating: -; AcousticRating: -; AllplanAttributes - ash_lichte Raumhöhe: 2.500000; OKFF: 0
Gipsfaserplatten 2-lagig (BSK) | WUN-H2-E00-019 | CEILING | D1 0.001 m | 1116Dfl0000066562/04 | m² | Maler- und Lackierarbeiten | 4 | 0.001 | 0 | 1 | Bekleidung | D1 | 0 | 0 | NEW | 2.5 | AllplanAttributes - ash_lichte Raumhöhe: 2.500000; OKFF: 0
Gipsfaserplatten 2-lagig (BSK) | WUN-H2-E00-019 | CEILING | layer 0.036 m | 1116Dfl0000066557/01 | m² | Trockenbauarbeiten | 1 | 0.036 | 0 | 1 | Deckenfläche |  | 0 | 0 | NEW | 3.15 | AllplanAttributes - Bezeichnung: Gipsfaserplatten 2-lagig (BSK)
Gipsfaserplatten 2-lagig (BSK) | WUN-H2-E00-019 | CEILING | Installationshöhe 0.114 m | 1116Dfl0000066557/02 | m² | Trockenbauarbeiten | 2 | 0.114 | 0 | 1 | Bekleidung | Installationshöhe | 0 | 0 | NEW | 3.15 | Pset_CoveringCommon - FireRating: -; AcousticRating: -; AllplanAttributes - ash_lichte Raumhöhe: 3.150000
Gipsfaserplatten 2-lagig (BSK) | WUN-H2-E00-019 | CEILING | A1 0.1 m | 1116Dfl0000066557/03 | m² | Trockenbauarbeiten | 3 | 0.1 | 0 | 1 | Bekleidung | A1 | 0 | 0 | NEW | 3.15 | Pset_CoveringCommon - FireRating: -; AcousticRating: -; AllplanAttributes - ash_lichte Raumhöhe: 3.150000
Gipsfaserplatten 2-lagig (BSK) | WUN-H2-E00-019 | CEILING | D1 0.001 m | 1116Dfl0000066557/04 | m² | Maler- und Lackierarbeiten | 4 | 0.001 | 0 | 1 | Bekleidung | D1 | 0 | 0 | NEW | 3.15 | AllplanAttributes - ash_lichte Raumhöhe: 3.150000
Acrobyn | WUN-H2-E00-041 | CLADDING | 84 0.001 m | 1116Sfl0000430827/02 | m² | Maler- und Lackierarbeiten | 2 | 0.001 | 0 | 1 | Seitenfläche | 84 | 0 | 0 | NEW | AllplanAttributes - Bezeichnung: Acrobyn
Acrobyn | WUN-H2-E00-041 | CLADDING | 84 0.001 m | 1116Sfl0000430239/02 | m² | Maler- und Lackierarbeiten | 2 | 0.001 | 0 | 1 | Seitenfläche | 84 | 0 | 0 | NEW | AllplanAttributes - Bezeichnung: Acrobyn
PVC Bahnenware Holzoptik | WUN-H2-E00-041 | FLOORING | Ku1 0.2 m | 1116Bfl0000065324/01 | m² | Bodenbelagsarbeiten | 1 | 0.2 | 0 | 1 | Bodenfläche | Ku1 | 0 | 0 | NEW | AllplanAttributes - Bezeichnung: PVC Bahnenware Holzoptik; Raumnr. Bauherr: 2.11_A2_02; ash B_Aufbau: B1; ash B_Rutschhemmung: R9
Gipsfaserplatten 2-lagig (BSK) | WUN-H2-E00-041 | CEILING | layer 0.036 m | 1116Dfl0000065325/01 | m² | Trockenbauarbeiten | 1 | 0.036 | 0 | 1 | Deckenfläche |  | 0 | 0 | NEW | 3.15 | AllplanAttributes - Bezeichnung: Gipsfaserplatten 2-lagig (BSK)
Gipsfaserplatten 2-lagig (BSK) | WUN-H2-E00-041 | CEILING | Installationshöhe 0.114 m | 1116Dfl0000065325/02 | m² | Trockenbauarbeiten | 2 | 0.114 | 0 | 1 | Bekleidung | Installationshöhe | 0 | 0 | NEW | 3.15 | Pset_CoveringCommon - FireRating: -; AcousticRating: -; AllplanAttributes - ash_lichte Raumhöhe: 3.150000
Gipsfaserplatten 2-lagig (BSK) | WUN-H2-E00-041 | CEILING | A1 0.1 m | 1116Dfl0000065325/03 | m² | Trockenbauarbeiten | 3 | 0.1 | 0 | 1 | Bekleidung | A1 | 0 | 0 | NEW | 3.15 | Pset_CoveringCommon - FireRating: -; AcousticRating: -; AllplanAttributes - ash_lichte Raumhöhe: 3.150000
Gipsfaserplatten 2-lagig (BSK) | WUN-H2-E00-041 | CEILING | D1 0.001 m | 1116Dfl0000065325/04 | m² | Maler- und Lackierarbeiten | 4 | 0.001 | 0 | 1 | Bekleidung | D1 | 0 | 0 | NEW | 3.15 | AllplanAttributes - ash_lichte Raumhöhe: 3.150000
Gipsfaserplatten 2-lagig (BSK) | WUN-H2-E00-041 | CEILING | layer 0.036 m | 1116Dfl0000065923/01 | m² | Trockenbauarbeiten | 1 | 0.036 | 0 | 1 | Deckenfläche |  | 0 | 0 | NEW | 2.5 | AllplanAttributes - Bezeichnung: Gipsfaserplatten 2-lagig (BSK)
Gipsfaserplatten 2-lagig (BSK) | WUN-H2-E00-041 | CEILING | Installationshöhe 0.764 m | 1116Dfl0000065923/02 | m² | Trockenbauarbeiten | 2 | 0.764 | 0 | 1 | Bekleidung | Installationshöhe | 0 | 0 | NEW | 2.5 | Pset_CoveringCommon - FireRating: für korrekte FläVisu; AllplanAttributes - ash_lichte Raumhöhe: 2.500000; OKFF: 0
Gipsfaserplatten 2-lagig (BSK) | WUN-H2-E00-041 | CEILING | A1 0.1 m | 1116Dfl0000065923/03 | m² | Trockenbauarbeiten | 3 | 0.1 | 0 | 1 | Bekleidung | A1 | 0 | 0 | NEW | 2.5 | Pset_CoveringCommon - FireRating: -; AcousticRating: -; AllplanAttributes - ash_lichte Raumhöhe: 2.500000; OKFF: 0
Gipsfaserplatten 2-lagig (BSK) | WUN-H2-E00-041 | CEILING | D1 0.001 m | 1116Dfl0000065923/04 | m² | Maler- und Lackierarbeiten | 4 | 0.001 | 0 | 1 | Bekleidung | D1 | 0 | 0 | NEW | 2.5 | AllplanAttributes - ash_lichte Raumhöhe: 2.500000; OKFF: 0
Acrobyn | WUN-H2-E00-023 | CLADDING | 84 0.001 m | 1116Sfl0000430221/02 | m² | Maler- und Lackierarbeiten | 2 | 0.001 | 0 | 1 | Seitenfläche | 84 | 0 | 0 | NEW | AllplanAttributes - Bezeichnung: Acrobyn
Acrobyn | WUN-H2-E00-023 | CLADDING | 84 0.001 m | 1116Sfl0000430233/02 | m² | Maler- und Lackierarbeiten | 2 | 0.001 | 0 | 1 | Seitenfläche | 84 | 0 | 0 | NEW | AllplanAttributes - Bezeichnung: Acrobyn
PVC Bahnenware Holzoptik | WUN-H2-E00-023 | FLOORING | Ku1 0.2 m | 1116Bfl0000065278/01 | m² | Bodenbelagsarbeiten | 1 | 0.2 | 0 | 1 | Bodenfläche | Ku1 | 0 | 0 | NEW | AllplanAttributes - Bezeichnung: PVC Bahnenware Holzoptik; Raumnr. Bauherr: 2.11_A2_02; ash B_Aufbau: B1; ash B_Rutschhemmung: R9
Gipsfaserplatten 2-lagig (BSK) | WUN-H2-E00-023 | CEILING | layer 0.036 m | 1116Dfl0000065935/01 | m² | Trockenbauarbeiten | 1 | 0.036 | 0 | 1 | Deckenfläche |  | 0 | 0 | NEW | 2.5 | AllplanAttributes - Bezeichnung: Gipsfaserplatten 2-lagig (BSK)
Gipsfaserplatten 2-lagig (BSK) | WUN-H2-E00-023 | CEILING | Installationshöhe 0.764 m | 1116Dfl0000065935/02 | m² | Trockenbauarbeiten | 2 | 0.764 | 0 | 1 | Bekleidung | Installationshöhe | 0 | 0 | NEW | 2.5 | Pset_CoveringCommon - FireRating: für korrekte FläVisu; AllplanAttributes - ash_lichte Raumhöhe: 2.500000; OKFF: 0
Gipsfaserplatten 2-lagig (BSK) | WUN-H2-E00-023 | CEILING | A1 0.1 m | 1116Dfl0000065935/03 | m² | Trockenbauarbeiten | 3 | 0.1 | 0 | 1 | Bekleidung | A1 | 0 | 0 | NEW | 2.5 | Pset_CoveringCommon - FireRating: -; AcousticRating: -; AllplanAttributes - ash_lichte Raumhöhe: 2.500000; OKFF: 0
Gipsfaserplatten 2-lagig (BSK) | WUN-H2-E00-023 | CEILING | D1 0.001 m | 1116Dfl0000065935/04 | m² | Maler- und Lackierarbeiten | 4 | 0.001 | 0 | 1 | Bekleidung | D1 | 0 | 0 | NEW | 2.5 | AllplanAttributes - ash_lichte Raumhöhe: 2.500000; OKFF: 0
Gipsfaserplatten 2-lagig (BSK) | WUN-H2-E00-023 | CEILING | layer 0.036 m | 1116Dfl0000065279/01 | m² | Trockenbauarbeiten | 1 | 0.036 | 0 | 1 | Deckenfläche |  | 0 | 0 | NEW | 3.15 | AllplanAttributes - Bezeichnung: Gipsfaserplatten 2-lagig (BSK)
Gipsfaserplatten 2-lagig (BSK) | WUN-H2-E00-023 | CEILING | Installationshöhe 0.114 m | 1116Dfl0000065279/02 | m² | Trockenbauarbeiten | 2 | 0.114 | 0 | 1 | Bekleidung | Installationshöhe | 0 | 0 | NEW | 3.15 | Pset_CoveringCommon - FireRating: -; AcousticRating: -; AllplanAttributes - ash_lichte Raumhöhe: 3.150000
Gipsfaserplatten 2-lagig (BSK) | WUN-H2-E00-023 | CEILING | A1 0.1 m | 1116Dfl0000065279/03 | m² | Trockenbauarbeiten | 3 | 0.1 | 0 | 1 | Bekleidung | A1 | 0 | 0 | NEW | 3.15 | Pset_CoveringCommon - FireRating: -; AcousticRating: -; AllplanAttributes - ash_lichte Raumhöhe: 3.150000
Gipsfaserplatten 2-lagig (BSK) | WUN-H2-E00-023 | CEILING | D1 0.001 m | 1116Dfl0000065279/04 | m² | Maler- und Lackierarbeiten | 4 | 0.001 | 0 | 1 | Bekleidung | D1 | 0 | 0 | NEW | 3.15 | AllplanAttributes - ash_lichte Raumhöhe: 3.150000
PVC Bahnenware Holzoptik | WUN-H2-E00-060 | FLOORING | Ku1 0.2 m | 1116Bfl0000065605/01 | m² | Bodenbelagsarbeiten | 1 | 0.2 | 0 | 1 | Bodenfläche | Ku1 | 0 | 0 | NEW | AllplanAttributes - Bezeichnung: PVC Bahnenware Holzoptik; Raumnr. Bauherr: 2.11_A2_02; ash B_Aufbau: B1; ash B_Rutschhemmung: R9
Gipsfaserplatten 2-lagig (BSK) | WUN-H2-E00-060 | CEILING | layer 0.036 m | 1116Dfl0000951338/01 | m² | Trockenbauarbeiten | 1 | 0.036 | 0 | 1 | Deckenfläche |  | 0 | 0 | NEW | 2.5 | AllplanAttributes - Bezeichnung: Gipsfaserplatten 2-lagig (BSK)
Gipsfaserplatten 2-lagig (BSK) | WUN-H2-E00-060 | CEILING | Installationshöhe 0.714 m | 1116Dfl0000951338/02 | m² | Trockenbauarbeiten | 2 | 0.714 | 0 | 1 | Bekleidung | Installationshöhe | 0 | 0 | NEW | 2.5 | Pset_CoveringCommon - FireRating: für korrekte FläVisu; AllplanAttributes - ash_lichte Raumhöhe: 2.500000; OKFF: 0
Akustikdecke gelocht | WUN-H2-E00-060 | CEILING | Aa 0.15 m | 1116Dfl0000951338/03 | m² | Trockenbauarbeiten | 3 | 0.15 | 0 | 1 | Bekleidung | Aa | 0 | 0 | NEW | 2.5 | AllplanAttributes - Bezeichnung: Akustikdecke gelocht; ash_lichte Raumhöhe: 2.500000; OKFF: 0; Pset_CoveringCommon - FireRating: -; AcousticRating: -
Gipsfaserplatten 2-lagig (BSK) | WUN-H2-E00-060 | CEILING | D1 0.001 m | 1116Dfl0000951338/04 | m² | Maler- und Lackierarbeiten | 4 | 0.001 | 0 | 1 | Bekleidung | D1 | 0 | 0 | NEW | 2.5 | AllplanAttributes - ash_lichte Raumhöhe: 2.500000; OKFF: 0
Gipsfaserplatten 2-lagig (BSK) | WUN-H2-E00-060 | CEILING | layer 0.036 m | 1116Dfl0000065903/01 | m² | Trockenbauarbeiten | 1 | 0.036 | 0 | 1 | Deckenfläche |  | 0 | 0 | NEW | 2.5 | AllplanAttributes - Bezeichnung: Gipsfaserplatten 2-lagig (BSK)
Gipsfaserplatten 2-lagig (BSK) | WUN-H2-E00-060 | CEILING | Installationshöhe 0.714 m | 1116Dfl0000065903/02 | m² | Trockenbauarbeiten | 2 | 0.714 | 0 | 1 | Bekleidung | Installationshöhe | 0 | 0 | NEW | 2.5 | Pset_CoveringCommon - FireRating: für korrekte FläVisu; AllplanAttributes - ash_lichte Raumhöhe: 2.500000; OKFF: 0
Gipsfaserplatten 2-lagig (BSK) | WUN-H2-E00-060 | CEILING | A1 0.15 m | 1116Dfl0000065903/03 | m² | Trockenbauarbeiten | 3 | 0.15 | 0 | 1 | Bekleidung | A1 | 0 | 0 | NEW | 2.5 | Pset_CoveringCommon - FireRating: -; AcousticRating: -; AllplanAttributes - ash_lichte Raumhöhe: 2.500000; OKFF: 0
Gipsfaserplatten 2-lagig (BSK) | WUN-H2-E00-060 | CEILING | D1 0.001 m | 1116Dfl0000065903/04 | m² | Maler- und Lackierarbeiten | 4 | 0.001 | 0 | 1 | Bekleidung | D1 | 0 | 0 | NEW | 2.5 | AllplanAttributes - ash_lichte Raumhöhe: 2.500000; OKFF: 0
Gipsfaserplatten 2-lagig (BSK) | WUN-H2-E00-060 | CEILING | layer 0.036 m | 1116Dfl0000065606/01 | m² | Trockenbauarbeiten | 1 | 0.036 | 0 | 1 | Deckenfläche |  | 0 | 0 | NEW | 3.1 | AllplanAttributes - Bezeichnung: Gipsfaserplatten 2-lagig (BSK)
Gipsfaserplatten 2-lagig (BSK) | WUN-H2-E00-060 | CEILING | Installationshöhe 0.164 m | 1116Dfl0000065606/02 | m² | Trockenbauarbeiten | 2 | 0.164 | 0 | 1 | Bekleidung | Installationshöhe | 0 | 0 | NEW | 3.1 | Pset_CoveringCommon - FireRating: -; AcousticRating: -; AllplanAttributes - ash_lichte Raumhöhe: 3.100000
Gipsfaserplatten 2-lagig (BSK) | WUN-H2-E00-060 | CEILING | A1 0.1 m | 1116Dfl0000065606/03 | m² | Trockenbauarbeiten | 3 | 0.1 | 0 | 1 | Bekleidung | A1 | 0 | 0 | NEW | 3.1 | Pset_CoveringCommon - FireRating: -; AcousticRating: -; AllplanAttributes - ash_lichte Raumhöhe: 3.100000
Gipsfaserplatten 2-lagig (BSK) | WUN-H2-E00-060 | CEILING | D1 0.001 m | 1116Dfl0000065606/04 | m² | Maler- und Lackierarbeiten | 4 | 0.001 | 0 | 1 | Bekleidung | D1 | 0 | 0 | NEW | 3.1 | AllplanAttributes - ash_lichte Raumhöhe: 3.100000
PVC Bahnenware Holzoptik | WUN-H2-E00-061 | FLOORING | Ku1 0.2 m | 1116Bfl0000065609/01 | m² | Bodenbelagsarbeiten | 1 | 0.2 | 0 | 1 | Bodenfläche | Ku1 | 0 | 0 | NEW | AllplanAttributes - Bezeichnung: PVC Bahnenware Holzoptik; Raumnr. Bauherr: 2.11_A2_02; ash B_Aufbau: B1; ash B_Rutschhemmung: R9
Gipsfaserplatten 2-lagig (BSK) | WUN-H2-E00-061 | CEILING | layer 0.036 m | 1116Dfl0000065610/01 | m² | Trockenbauarbeiten | 1 | 0.036 | 0 | 1 | Deckenfläche |  | 0 | 0 | NEW | 3.1 | AllplanAttributes - Bezeichnung: Gipsfaserplatten 2-lagig (BSK)
Gipsfaserplatten 2-lagig (BSK) | WUN-H2-E00-061 | CEILING | Installationshöhe 0.164 m | 1116Dfl0000065610/02 | m² | Trockenbauarbeiten | 2 | 0.164 | 0 | 1 | Bekleidung | Installationshöhe | 0 | 0 | NEW | 3.1 | Pset_CoveringCommon - FireRating: -; AcousticRating: -; AllplanAttributes - ash_lichte Raumhöhe: 3.100000
Gipsfaserplatten 2-lagig (BSK) | WUN-H2-E00-061 | CEILING | A1 0.1 m | 1116Dfl0000065610/03 | m² | Trockenbauarbeiten | 3 | 0.1 | 0 | 1 | Bekleidung | A1 | 0 | 0 | NEW | 3.1 | Pset_CoveringCommon - FireRating: -; AcousticRating: -; AllplanAttributes - ash_lichte Raumhöhe: 3.100000
Gipsfaserplatten 2-lagig (BSK) | WUN-H2-E00-061 | CEILING | D1 0.001 m | 1116Dfl0000065610/04 | m² | Maler- und Lackierarbeiten | 4 | 0.001 | 0 | 1 | Bekleidung | D1 | 0 | 0 | NEW | 3.1 | AllplanAttributes - ash_lichte Raumhöhe: 3.100000
Gipsfaserplatten 2-lagig (BSK) | WUN-H2-E00-061 | CEILING | layer 0.036 m | 1116Dfl0000950881/01 | m² | Trockenbauarbeiten | 1 | 0.036 | 0 | 1 | Deckenfläche |  | 0 | 0 | NEW | 2.5 | AllplanAttributes - Bezeichnung: Gipsfaserplatten 2-lagig (BSK)
Gipsfaserplatten 2-lagig (BSK) | WUN-H2-E00-061 | CEILING | Installationshöhe 0.714 m | 1116Dfl0000950881/02 | m² | Trockenbauarbeiten | 2 | 0.714 | 0 | 1 | Bekleidung | Installationshöhe | 0 | 0 | NEW | 2.5 | Pset_CoveringCommon - FireRating: für korrekte FläVisu; AllplanAttributes - ash_lichte Raumhöhe: 2.500000; OKFF: 0
Akustikdecke gelocht | WUN-H2-E00-061 | CEILING | Aa 0.15 m | 1116Dfl0000950881/03 | m² | Trockenbauarbeiten | 3 | 0.15 | 0 | 1 | Bekleidung | Aa | 0 | 0 | NEW | 2.5 | AllplanAttributes - Bezeichnung: Akustikdecke gelocht; ash_lichte Raumhöhe: 2.500000; OKFF: 0; Pset_CoveringCommon - FireRating: -; AcousticRating: -
Gipsfaserplatten 2-lagig (BSK) | WUN-H2-E00-061 | CEILING | D1 0.001 m | 1116Dfl0000950881/04 | m² | Maler- und Lackierarbeiten | 4 | 0.001 | 0 | 1 | Bekleidung | D1 | 0 | 0 | NEW | 2.5 | AllplanAttributes - ash_lichte Raumhöhe: 2.500000; OKFF: 0
Gipsfaserplatten 2-lagig (BSK) | WUN-H2-E00-061 | CEILING | layer 0.036 m | 1116Dfl0000065901/01 | m² | Trockenbauarbeiten | 1 | 0.036 | 0 | 1 | Deckenfläche |  | 0 | 0 | NEW | 2.5 | AllplanAttributes - Bezeichnung: Gipsfaserplatten 2-lagig (BSK)
Gipsfaserplatten 2-lagig (BSK) | WUN-H2-E00-061 | CEILING | Installationshöhe 0.714 m | 1116Dfl0000065901/02 | m² | Trockenbauarbeiten | 2 | 0.714 | 0 | 1 | Bekleidung | Installationshöhe | 0 | 0 | NEW | 2.5 | Pset_CoveringCommon - FireRating: für korrekte FläVisu; AllplanAttributes - ash_lichte Raumhöhe: 2.500000; OKFF: 0
Gipsfaserplatten 2-lagig (BSK) | WUN-H2-E00-061 | CEILING | A1 0.15 m | 1116Dfl0000065901/03 | m² | Trockenbauarbeiten | 3 | 0.15 | 0 | 1 | Bekleidung | A1 | 0 | 0 | NEW | 2.5 | Pset_CoveringCommon - FireRating: -; AcousticRating: -; AllplanAttributes - ash_lichte Raumhöhe: 2.500000; OKFF: 0
Gipsfaserplatten 2-lagig (BSK) | WUN-H2-E00-061 | CEILING | D1 0.001 m | 1116Dfl0000065901/04 | m² | Maler- und Lackierarbeiten | 4 | 0.001 | 0 | 1 | Bekleidung | D1 | 0 | 0 | NEW | 2.5 | AllplanAttributes - ash_lichte Raumhöhe: 2.500000; OKFF: 0
PVC Bahnenware Holzoptik | WUN-H2-E00-003 | FLOORING | Ku1 0.2 m | 1116Bfl0000065593/01 | m² | Bodenbelagsarbeiten | 1 | 0.2 | 0 | 1 | Bodenfläche | Ku1 | 0 | 0 | NEW | AllplanAttributes - Bezeichnung: PVC Bahnenware Holzoptik; Raumnr. Bauherr: 2.11_A2_02; ash B_Aufbau: B1; ash B_Rutschhemmung: R9
Gipsfaserplatten 2-lagig (BSK) | WUN-H2-E00-003 | CEILING | layer 0.036 m | 1116Dfl0000950162/01 | m² | Trockenbauarbeiten | 1 | 0.036 | 0 | 1 | Deckenfläche |  | 0 | 0 | NEW | 2.5 | AllplanAttributes - Bezeichnung: Gipsfaserplatten 2-lagig (BSK)
Gipsfaserplatten 2-lagig (BSK) | WUN-H2-E00-003 | CEILING | Installationshöhe 0.714 m | 1116Dfl0000950162/02 | m² | Trockenbauarbeiten | 2 | 0.714 | 0 | 1 | Bekleidung | Installationshöhe | 0 | 0 | NEW | 2.5 | Pset_CoveringCommon - FireRating: für korrekte FläVisu; AllplanAttributes - ash_lichte Raumhöhe: 2.500000; OKFF: 0
Akustikdecke gelocht | WUN-H2-E00-003 | CEILING | Aa 0.15 m | 1116Dfl0000950162/03 | m² | Trockenbauarbeiten | 3 | 0.15 | 0 | 1 | Bekleidung | Aa | 0 | 0 | NEW | 2.5 | AllplanAttributes - Bezeichnung: Akustikdecke gelocht; ash_lichte Raumhöhe: 2.500000; OKFF: 0; Pset_CoveringCommon - FireRating: -; AcousticRating: -
Gipsfaserplatten 2-lagig (BSK) | WUN-H2-E00-003 | CEILING | D1 0.001 m | 1116Dfl0000950162/04 | m² | Maler- und Lackierarbeiten | 4 | 0.001 | 0 | 1 | Bekleidung | D1 | 0 | 0 | NEW | 2.5 | AllplanAttributes - ash_lichte Raumhöhe: 2.500000; OKFF: 0
Gipsfaserplatten 2-lagig (BSK) | WUN-H2-E00-003 | CEILING | layer 0.036 m | 1116Dfl0000950173/01 | m² | Trockenbauarbeiten | 1 | 0.036 | 0 | 1 | Deckenfläche |  | 0 | 0 | NEW | 2.5 | AllplanAttributes - Bezeichnung: Gipsfaserplatten 2-lagig (BSK)
Gipsfaserplatten 2-lagig (BSK) | WUN-H2-E00-003 | CEILING | Installationshöhe 0.764 m | 1116Dfl0000950173/02 | m² | Trockenbauarbeiten | 2 | 0.764 | 0 | 1 | Bekleidung | Installationshöhe | 0 | 0 | NEW | 2.5 | Pset_CoveringCommon - FireRating: für korrekte FläVisu; AllplanAttributes - ash_lichte Raumhöhe: 2.500000; OKFF: 0
Kühldecke gelocht | WUN-H2-E00-003 | CEILING | H7b 0.1 m | 1116Dfl0000950173/03 | m² | Trockenbauarbeiten | 3 | 0.1 | 0 | 1 | Bekleidung | H7b | 0 | 0 | NEW | 2.5 | AllplanAttributes - Bezeichnung: Kühldecke gelocht; ash_lichte Raumhöhe: 2.500000; OKFF: 0; Pset_CoveringCommon - FireRating: -; AcousticRating: -
Gipsfaserplatten 2-lagig (BSK) | WUN-H2-E00-003 | CEILING | D1 0.001 m | 1116Dfl0000950173/04 | m² | Maler- und Lackierarbeiten | 4 | 0.001 | 0 | 1 | Bekleidung | D1 | 0 | 0 | NEW | 2.5 | AllplanAttributes - ash_lichte Raumhöhe: 2.500000; OKFF: 0
Gipsfaserplatten 2-lagig (BSK) | WUN-H2-E00-003 | CEILING | layer 0.036 m | 1116Dfl0000065594/01 | m² | Trockenbauarbeiten | 1 | 0.036 | 0 | 1 | Deckenfläche |  | 0 | 0 | NEW | 3.1 | AllplanAttributes - Bezeichnung: Gipsfaserplatten 2-lagig (BSK)
Gipsfaserplatten 2-lagig (BSK) | WUN-H2-E00-003 | CEILING | Installationshöhe 0.164 m | 1116Dfl0000065594/02 | m² | Trockenbauarbeiten | 2 | 0.164 | 0 | 1 | Bekleidung | Installationshöhe | 0 | 0 | NEW | 3.1 | Pset_CoveringCommon - FireRating: -; AcousticRating: -; AllplanAttributes - ash_lichte Raumhöhe: 3.100000
Gipsfaserplatten 2-lagig (BSK) | WUN-H2-E00-003 | CEILING | A1 0.1 m | 1116Dfl0000065594/03 | m² | Trockenbauarbeiten | 3 | 0.1 | 0 | 1 | Bekleidung | A1 | 0 | 0 | NEW | 3.1 | Pset_CoveringCommon - FireRating: -; AcousticRating: -; AllplanAttributes - ash_lichte Raumhöhe: 3.100000
Gipsfaserplatten 2-lagig (BSK) | WUN-H2-E00-003 | CEILING | D1 0.001 m | 1116Dfl0000065594/04 | m² | Maler- und Lackierarbeiten | 4 | 0.001 | 0 | 1 | Bekleidung | D1 | 0 | 0 | NEW | 3.1 | AllplanAttributes - ash_lichte Raumhöhe: 3.100000
Gipsfaserplatten 2-lagig (BSK) | WUN-H2-E00-003 | CEILING | layer 0.036 m | 1116Dfl0000065905/01 | m² | Trockenbauarbeiten | 1 | 0.036 | 0 | 1 | Deckenfläche |  | 0 | 0 | NEW | 2.5 | AllplanAttributes - Bezeichnung: Gipsfaserplatten 2-lagig (BSK)
Gipsfaserplatten 2-lagig (BSK) | WUN-H2-E00-003 | CEILING | Installationshöhe 0.714 m | 1116Dfl0000065905/02 | m² | Trockenbauarbeiten | 2 | 0.714 | 0 | 1 | Bekleidung | Installationshöhe | 0 | 0 | NEW | 2.5 | Pset_CoveringCommon - FireRating: für korrekte FläVisu; AllplanAttributes - ash_lichte Raumhöhe: 2.500000; OKFF: 0
Gipsfaserplatten 2-lagig (BSK) | WUN-H2-E00-003 | CEILING | A1 0.15 m | 1116Dfl0000065905/03 | m² | Trockenbauarbeiten | 3 | 0.15 | 0 | 1 | Bekleidung | A1 | 0 | 0 | NEW | 2.5 | Pset_CoveringCommon - FireRating: -; AcousticRating: -; AllplanAttributes - ash_lichte Raumhöhe: 2.500000; OKFF: 0
Gipsfaserplatten 2-lagig (BSK) | WUN-H2-E00-003 | CEILING | D1 0.001 m | 1116Dfl0000065905/04 | m² | Maler- und Lackierarbeiten | 4 | 0.001 | 0 | 1 | Bekleidung | D1 | 0 | 0 | NEW | 2.5 | AllplanAttributes - ash_lichte Raumhöhe: 2.500000; OKFF: 0
PVC Bahnenware Holzoptik | WUN-H2-E00-008 | FLOORING | Ku1 0.2 m | 1116Bfl0000065573/01 | m² | Bodenbelagsarbeiten | 1 | 0.2 | 0 | 1 | Bodenfläche | Ku1 | 0 | 0 | NEW | AllplanAttributes - Bezeichnung: PVC Bahnenware Holzoptik; Raumnr. Bauherr: 2.11_A2_02; ash B_Aufbau: B1; ash B_Rutschhemmung: R9
Gipsfaserplatten 2-lagig (BSK) | WUN-H2-E00-008 | CEILING | layer 0.036 m | 1116Dfl0000492246/01 | m² | Trockenbauarbeiten | 1 | 0.036 | 0 | 1 | Deckenfläche |  | 0 | 0 | NEW | 2.75 | AllplanAttributes - Bezeichnung: Gipsfaserplatten 2-lagig (BSK)
Gipsfaserplatten 2-lagig (BSK) | WUN-H2-E00-008 | CEILING | Installationshöhe 0.424 m | 1116Dfl0000492246/02 | m² | Trockenbauarbeiten | 2 | 0.424 | 0 | 1 | Bekleidung | Installationshöhe | 0 | 0 | NEW | 2.75 | Pset_CoveringCommon - FireRating: für korrekte FläVisu; AllplanAttributes - ash_lichte Raumhöhe: 2.750000; OKFF: 0
Gipsfaserplatten 2-lagig (BSK) | WUN-H2-E00-008 | CEILING | Aa 0.15 m | 1116Dfl0000492246/03 | m² | Trockenbauarbeiten | 3 | 0.15 | 0 | 1 | Bekleidung | Aa | 0 | 0 | NEW | 2.75 | Pset_CoveringCommon - FireRating: -; AcousticRating: -; AllplanAttributes - ash_lichte Raumhöhe: 2.750000; OKFF: 0
Gipsfaserplatten 2-lagig (BSK) | WUN-H2-E00-008 | CEILING | D1 0.001 m | 1116Dfl0000492246/04 | m² | Maler- und Lackierarbeiten | 4 | 0.001 | 0 | 1 | Bekleidung | D1 | 0 | 0 | NEW | 2.75 | AllplanAttributes - ash_lichte Raumhöhe: 2.750000; OKFF: 0
Gipsfaserplatten 2-lagig (BSK) | WUN-H2-E00-008 | CEILING | layer 0.036 m | 1116Dfl0000492699/01 | m² | Trockenbauarbeiten | 1 | 0.036 | 0 | 1 | Deckenfläche |  | 0 | 0 | NEW | 2.75 | AllplanAttributes - Bezeichnung: Gipsfaserplatten 2-lagig (BSK)
Gipsfaserplatten 2-lagig (BSK) | WUN-H2-E00-008 | CEILING | Installationshöhe 0.464 m | 1116Dfl0000492699/02 | m² | Trockenbauarbeiten | 2 | 0.464 | 0 | 1 | Bekleidung | Installationshöhe | 0 | 0 | NEW | 2.75 | Pset_CoveringCommon - FireRating: für korrekte FläVisu; AllplanAttributes - ash_lichte Raumhöhe: 2.750000; OKFF: 0
Gipsfaserplatten 2-lagig (BSK) | WUN-H2-E00-008 | CEILING | A1 0.15 m | 1116Dfl0000492699/03 | m² | Trockenbauarbeiten | 3 | 0.15 | 0 | 1 | Bekleidung | A1 | 0 | 0 | NEW | 2.75 | Pset_CoveringCommon - FireRating: -; AcousticRating: -; AllplanAttributes - ash_lichte Raumhöhe: 2.750000; OKFF: 0
Gipsfaserplatten 2-lagig (BSK) | WUN-H2-E00-008 | CEILING | D1 0.001 m | 1116Dfl0000492699/04 | m² | Maler- und Lackierarbeiten | 4 | 0.001 | 0 | 1 | Bekleidung | D1 | 0 | 0 | NEW | 2.75 | AllplanAttributes - ash_lichte Raumhöhe: 2.750000; OKFF: 0
Gipsfaserplatten 2-lagig (BSK) | WUN-H2-E00-008 | CEILING | layer 0.036 m | 1116Dfl0000492697/01 | m² | Trockenbauarbeiten | 1 | 0.036 | 0 | 1 | Deckenfläche |  | 0 | 0 | NEW | 2.75 | AllplanAttributes - Bezeichnung: Gipsfaserplatten 2-lagig (BSK)
Gipsfaserplatten 2-lagig (BSK) | WUN-H2-E00-008 | CEILING | Installationshöhe 0.464 m | 1116Dfl0000492697/02 | m² | Trockenbauarbeiten | 2 | 0.464 | 0 | 1 | Bekleidung | Installationshöhe | 0 | 0 | NEW | 2.75 | Pset_CoveringCommon - FireRating: für korrekte FläVisu; AllplanAttributes - ash_lichte Raumhöhe: 2.750000; OKFF: 0
Gipsfaserplatten 2-lagig (BSK) | WUN-H2-E00-008 | CEILING | Aa 0.15 m | 1116Dfl0000492697/03 | m² | Trockenbauarbeiten | 3 | 0.15 | 0 | 1 | Bekleidung | Aa | 0 | 0 | NEW | 2.75 | Pset_CoveringCommon - FireRating: -; AcousticRating: -; AllplanAttributes - ash_lichte Raumhöhe: 2.750000; OKFF: 0
Gipsfaserplatten 2-lagig (BSK) | WUN-H2-E00-008 | CEILING | D1 0.001 m | 1116Dfl0000492697/04 | m² | Maler- und Lackierarbeiten | 4 | 0.001 | 0 | 1 | Bekleidung | D1 | 0 | 0 | NEW | 2.75 | AllplanAttributes - ash_lichte Raumhöhe: 2.750000; OKFF: 0
Gipsfaserplatten 2-lagig (BSK) | WUN-H2-E00-008 | CEILING | layer 0.036 m | 1116Dfl0000492248/01 | m² | Trockenbauarbeiten | 1 | 0.036 | 0 | 1 | Deckenfläche |  | 0 | 0 | NEW | 2.75 | AllplanAttributes - Bezeichnung: Gipsfaserplatten 2-lagig (BSK)
Gipsfaserplatten 2-lagig (BSK) | WUN-H2-E00-008 | CEILING | Installationshöhe 0.424 m | 1116Dfl0000492248/02 | m² | Trockenbauarbeiten | 2 | 0.424 | 0 | 1 | Bekleidung | Installationshöhe | 0 | 0 | NEW | 2.75 | Pset_CoveringCommon - FireRating: für korrekte FläVisu; AllplanAttributes - ash_lichte Raumhöhe: 2.750000; OKFF: 0
Gipsfaserplatten 2-lagig (BSK) | WUN-H2-E00-008 | CEILING | A1 0.15 m | 1116Dfl0000492248/03 | m² | Trockenbauarbeiten | 3 | 0.15 | 0 | 1 | Bekleidung | A1 | 0 | 0 | NEW | 2.75 | Pset_CoveringCommon - FireRating: -; AcousticRating: -; AllplanAttributes - ash_lichte Raumhöhe: 2.750000; OKFF: 0
Gipsfaserplatten 2-lagig (BSK) | WUN-H2-E00-008 | CEILING | D1 0.001 m | 1116Dfl0000492248/04 | m² | Maler- und Lackierarbeiten | 4 | 0.001 | 0 | 1 | Bekleidung | D1 | 0 | 0 | NEW | 2.75 | AllplanAttributes - ash_lichte Raumhöhe: 2.750000; OKFF: 0
Gipsfaserplatten 2-lagig (BSK) | WUN-H2-E00-008 | CEILING | layer 0.036 m | 1116Dfl0000492244/01 | m² | Trockenbauarbeiten | 1 | 0.036 | 0 | 1 | Deckenfläche |  | 0 | 0 | NEW | 3.1 | AllplanAttributes - Bezeichnung: Gipsfaserplatten 2-lagig (BSK)
Gipsfaserplatten 2-lagig (BSK) | WUN-H2-E00-008 | CEILING | Installationshöhe 0.124 m | 1116Dfl0000492244/02 | m² | Trockenbauarbeiten | 2 | 0.124 | 0 | 1 | Bekleidung | Installationshöhe | 0 | 0 | NEW | 3.1 | Pset_CoveringCommon - FireRating: für korrekte FläVisu; AllplanAttributes - ash_lichte Raumhöhe: 3.100000; OKFF: 0
Gipsfaserplatten 2-lagig (BSK) | WUN-H2-E00-008 | CEILING | A1 0.1 m | 1116Dfl0000492244/03 | m² | Trockenbauarbeiten | 3 | 0.1 | 0 | 1 | Bekleidung | A1 | 0 | 0 | NEW | 3.1 | Pset_CoveringCommon - FireRating: -; AcousticRating: -; AllplanAttributes - ash_lichte Raumhöhe: 3.100000; OKFF: 0
Gipsfaserplatten 2-lagig (BSK) | WUN-H2-E00-008 | CEILING | D1 0.001 m | 1116Dfl0000492244/04 | m² | Maler- und Lackierarbeiten | 4 | 0.001 | 0 | 1 | Bekleidung | D1 | 0 | 0 | NEW | 3.1 | AllplanAttributes - ash_lichte Raumhöhe: 3.100000; OKFF: 0
Gipsfaserplatten 2-lagig (BSK) | WUN-H2-E00-008 | CEILING | layer 0.036 m | 1116Dfl0000065574/01 | m² | Trockenbauarbeiten | 1 | 0.036 | 0 | 1 | Deckenfläche |  | 0 | 0 | NEW | 3.1 | AllplanAttributes - Bezeichnung: Gipsfaserplatten 2-lagig (BSK)
Gipsfaserplatten 2-lagig (BSK) | WUN-H2-E00-008 | CEILING | Installationshöhe 0.164 m | 1116Dfl0000065574/02 | m² | Trockenbauarbeiten | 2 | 0.164 | 0 | 1 | Bekleidung | Installationshöhe | 0 | 0 | NEW | 3.1 | Pset_CoveringCommon - FireRating: -; AcousticRating: -; AllplanAttributes - ash_lichte Raumhöhe: 3.100000
Gipsfaserplatten 2-lagig (BSK) | WUN-H2-E00-008 | CEILING | A1 0.1 m | 1116Dfl0000065574/03 | m² | Trockenbauarbeiten | 3 | 0.1 | 0 | 1 | Bekleidung | A1 | 0 | 0 | NEW | 3.1 | Pset_CoveringCommon - FireRating: -; AcousticRating: -; AllplanAttributes - ash_lichte Raumhöhe: 3.100000
Gipsfaserplatten 2-lagig (BSK) | WUN-H2-E00-008 | CEILING | D1 0.001 m | 1116Dfl0000065574/04 | m² | Maler- und Lackierarbeiten | 4 | 0.001 | 0 | 1 | Bekleidung | D1 | 0 | 0 | NEW | 3.1 | AllplanAttributes - ash_lichte Raumhöhe: 3.100000
PVC Bahnenware Holzoptik | WUN-H2-E00-048 | FLOORING | Ku1 0.2 m | 1116Bfl0000065314/01 | m² | Bodenbelagsarbeiten | 1 | 0.2 | 0 | 1 | Bodenfläche | Ku1 | 0 | 0 | NEW | AllplanAttributes - Bezeichnung: PVC Bahnenware Holzoptik; Raumnr. Bauherr: 2.11_A2_02; ash B_Aufbau: B1; ash B_Rutschhemmung: R9
Gipsfaserplatten 2-lagig (BSK) | WUN-H2-E00-048 | CEILING | layer 0.036 m | 1116Dfl0000065947/01 | m² | Trockenbauarbeiten | 1 | 0.036 | 0 | 1 | Deckenfläche |  | 0 | 0 | NEW | 2.5 | AllplanAttributes - Bezeichnung: Gipsfaserplatten 2-lagig (BSK)
Gipsfaserplatten 2-lagig (BSK) | WUN-H2-E00-048 | CEILING | Installationshöhe 0.724 m | 1116Dfl0000065947/02 | m² | Trockenbauarbeiten | 2 | 0.724 | 0 | 1 | Bekleidung | Installationshöhe | 0 | 0 | NEW | 2.5 | Pset_CoveringCommon - FireRating: für korrekte FläVisu; AllplanAttributes - ash_lichte Raumhöhe: 2.500000; OKFF: 0
Gipsfaserplatten 2-lagig (BSK) | WUN-H2-E00-048 | CEILING | A1 0.1 m | 1116Dfl0000065947/03 | m² | Trockenbauarbeiten | 3 | 0.1 | 0 | 1 | Bekleidung | A1 | 0 | 0 | NEW | 2.5 | Pset_CoveringCommon - FireRating: -; AcousticRating: -; AllplanAttributes - ash_lichte Raumhöhe: 2.500000; OKFF: 0
Gipsfaserplatten 2-lagig (BSK) | WUN-H2-E00-048 | CEILING | D1 0.001 m | 1116Dfl0000065947/04 | m² | Maler- und Lackierarbeiten | 4 | 0.001 | 0 | 1 | Bekleidung | D1 | 0 | 0 | NEW | 2.5 | AllplanAttributes - ash_lichte Raumhöhe: 2.500000; OKFF: 0
Gipsfaserplatten 2-lagig (BSK) | WUN-H2-E00-048 | CEILING | layer 0.036 m | 1116Dfl0000065315/01 | m² | Trockenbauarbeiten | 1 | 0.036 | 0 | 1 | Deckenfläche |  | 0 | 0 | NEW | 3.1 | AllplanAttributes - Bezeichnung: Gipsfaserplatten 2-lagig (BSK)
Gipsfaserplatten 2-lagig (BSK) | WUN-H2-E00-048 | CEILING | Installationshöhe 0.124 m | 1116Dfl0000065315/02 | m² | Trockenbauarbeiten | 2 | 0.124 | 0 | 1 | Bekleidung | Installationshöhe | 0 | 0 | NEW | 3.1 | Pset_CoveringCommon - FireRating: -; AcousticRating: -; AllplanAttributes - ash_lichte Raumhöhe: 3.100000
Gipsfaserplatten 2-lagig (BSK) | WUN-H2-E00-048 | CEILING | A1 0.1 m | 1116Dfl0000065315/03 | m² | Trockenbauarbeiten | 3 | 0.1 | 0 | 1 | Bekleidung | A1 | 0 | 0 | NEW | 3.1 | Pset_CoveringCommon - FireRating: -; AcousticRating: -; AllplanAttributes - ash_lichte Raumhöhe: 3.100000
Gipsfaserplatten 2-lagig (BSK) | WUN-H2-E00-048 | CEILING | D1 0.001 m | 1116Dfl0000065315/04 | m² | Maler- und Lackierarbeiten | 4 | 0.001 | 0 | 1 | Bekleidung | D1 | 0 | 0 | NEW | 3.1 | AllplanAttributes - ash_lichte Raumhöhe: 3.100000
PVC Bahnenware Holzoptik | WUN-H2-E00-050 | FLOORING | Ku1 0.2 m | 1116Bfl0000065316/01 | m² | Bodenbelagsarbeiten | 1 | 0.2 | 0 | 1 | Bodenfläche | Ku1 | 0 | 0 | NEW | AllplanAttributes - Bezeichnung: PVC Bahnenware Holzoptik; Raumnr. Bauherr: 2.11_A2_02; ash B_Aufbau: B1; ash B_Rutschhemmung: R9
Gipsfaserplatten 2-lagig (BSK) | WUN-H2-E00-050 | CEILING | layer 0.036 m | 1116Dfl0000065317/01 | m² | Trockenbauarbeiten | 1 | 0.036 | 0 | 1 | Deckenfläche |  | 0 | 0 | NEW | 3.1 | AllplanAttributes - Bezeichnung: Gipsfaserplatten 2-lagig (BSK)
Gipsfaserplatten 2-lagig (BSK) | WUN-H2-E00-050 | CEILING | Installationshöhe 0.124 m | 1116Dfl0000065317/02 | m² | Trockenbauarbeiten | 2 | 0.124 | 0 | 1 | Bekleidung | Installationshöhe | 0 | 0 | NEW | 3.1 | Pset_CoveringCommon - FireRating: -; AcousticRating: -; AllplanAttributes - ash_lichte Raumhöhe: 3.100000
Gipsfaserplatten 2-lagig (BSK) | WUN-H2-E00-050 | CEILING | A1 0.1 m | 1116Dfl0000065317/03 | m² | Trockenbauarbeiten | 3 | 0.1 | 0 | 1 | Bekleidung | A1 | 0 | 0 | NEW | 3.1 | Pset_CoveringCommon - FireRating: -; AcousticRating: -; AllplanAttributes - ash_lichte Raumhöhe: 3.100000
Gipsfaserplatten 2-lagig (BSK) | WUN-H2-E00-050 | CEILING | D1 0.001 m | 1116Dfl0000065317/04 | m² | Maler- und Lackierarbeiten | 4 | 0.001 | 0 | 1 | Bekleidung | D1 | 0 | 0 | NEW | 3.1 | AllplanAttributes - ash_lichte Raumhöhe: 3.100000
Gipsfaserplatten 2-lagig (BSK) | WUN-H2-E00-050 | CEILING | layer 0.036 m | 1116Dfl0000065949/01 | m² | Trockenbauarbeiten | 1 | 0.036 | 0 | 1 | Deckenfläche |  | 0 | 0 | NEW | 2.5 | AllplanAttributes - Bezeichnung: Gipsfaserplatten 2-lagig (BSK)
Gipsfaserplatten 2-lagig (BSK) | WUN-H2-E00-050 | CEILING | Installationshöhe 0.724 m | 1116Dfl0000065949/02 | m² | Trockenbauarbeiten | 2 | 0.724 | 0 | 1 | Bekleidung | Installationshöhe | 0 | 0 | NEW | 2.5 | Pset_CoveringCommon - FireRating: für korrekte FläVisu; AllplanAttributes - ash_lichte Raumhöhe: 2.500000; OKFF: 0
Gipsfaserplatten 2-lagig (BSK) | WUN-H2-E00-050 | CEILING | A1 0.1 m | 1116Dfl0000065949/03 | m² | Trockenbauarbeiten | 3 | 0.1 | 0 | 1 | Bekleidung | A1 | 0 | 0 | NEW | 2.5 | Pset_CoveringCommon - FireRating: -; AcousticRating: -; AllplanAttributes - ash_lichte Raumhöhe: 2.500000; OKFF: 0
Gipsfaserplatten 2-lagig (BSK) | WUN-H2-E00-050 | CEILING | D1 0.001 m | 1116Dfl0000065949/04 | m² | Maler- und Lackierarbeiten | 4 | 0.001 | 0 | 1 | Bekleidung | D1 | 0 | 0 | NEW | 2.5 | AllplanAttributes - ash_lichte Raumhöhe: 2.500000; OKFF: 0
PVC Bahnenware Holzoptik | WUN-H2-E00-055 | FLOORING | Ku1 0.2 m | 1116Bfl0000065578/01 | m² | Bodenbelagsarbeiten | 1 | 0.2 | 0 | 1 | Bodenfläche | Ku1 | 0 | 0 | NEW | AllplanAttributes - Bezeichnung: PVC Bahnenware Holzoptik; Raumnr. Bauherr: 2.11_A2_02; ash B_Aufbau: B1; ash B_Rutschhemmung: R9
Gipsfaserplatten 2-lagig (BSK) | WUN-H2-E00-055 | CEILING | layer 0.036 m | 1116Dfl0000462975/01 | m² | Trockenbauarbeiten | 1 | 0.036 | 0 | 1 | Deckenfläche |  | 0 | 0 | NEW | 2.75 | AllplanAttributes - Bezeichnung: Gipsfaserplatten 2-lagig (BSK)
Gipsfaserplatten 2-lagig (BSK) | WUN-H2-E00-055 | CEILING | Installationshöhe 0.424 m | 1116Dfl0000462975/02 | m² | Trockenbauarbeiten | 2 | 0.424 | 0 | 1 | Bekleidung | Installationshöhe | 0 | 0 | NEW | 2.75 | Pset_CoveringCommon - FireRating: für korrekte FläVisu; AllplanAttributes - ash_lichte Raumhöhe: 2.750000; OKFF: 0
Gipsfaserplatten 2-lagig (BSK) | WUN-H2-E00-055 | CEILING | A1 0.15 m | 1116Dfl0000462975/03 | m² | Trockenbauarbeiten | 3 | 0.15 | 0 | 1 | Bekleidung | A1 | 0 | 0 | NEW | 2.75 | Pset_CoveringCommon - FireRating: -; AcousticRating: -; AllplanAttributes - ash_lichte Raumhöhe: 2.750000; OKFF: 0
Gipsfaserplatten 2-lagig (BSK) | WUN-H2-E00-055 | CEILING | D1 0.001 m | 1116Dfl0000462975/04 | m² | Maler- und Lackierarbeiten | 4 | 0.001 | 0 | 1 | Bekleidung | D1 | 0 | 0 | NEW | 2.75 | AllplanAttributes - ash_lichte Raumhöhe: 2.750000; OKFF: 0
Gipsfaserplatten 2-lagig (BSK) | WUN-H2-E00-055 | CEILING | layer 0.036 m | 1116Dfl0000462977/01 | m² | Trockenbauarbeiten | 1 | 0.036 | 0 | 1 | Deckenfläche |  | 0 | 0 | NEW | 2.75 | AllplanAttributes - Bezeichnung: Gipsfaserplatten 2-lagig (BSK)
Gipsfaserplatten 2-lagig (BSK) | WUN-H2-E00-055 | CEILING | Installationshöhe 0.424 m | 1116Dfl0000462977/02 | m² | Trockenbauarbeiten | 2 | 0.424 | 0 | 1 | Bekleidung | Installationshöhe | 0 | 0 | NEW | 2.75 | Pset_CoveringCommon - FireRating: für korrekte FläVisu; AllplanAttributes - ash_lichte Raumhöhe: 2.750000; OKFF: 0
Gipsfaserplatten 2-lagig (BSK) | WUN-H2-E00-055 | CEILING | Aa 0.15 m | 1116Dfl0000462977/03 | m² | Trockenbauarbeiten | 3 | 0.15 | 0 | 1 | Bekleidung | Aa | 0 | 0 | NEW | 2.75 | Pset_CoveringCommon - FireRating: -; AcousticRating: -; AllplanAttributes - ash_lichte Raumhöhe: 2.750000; OKFF: 0
Gipsfaserplatten 2-lagig (BSK) | WUN-H2-E00-055 | CEILING | D1 0.001 m | 1116Dfl0000462977/04 | m² | Maler- und Lackierarbeiten | 4 | 0.001 | 0 | 1 | Bekleidung | D1 | 0 | 0 | NEW | 2.75 | AllplanAttributes - ash_lichte Raumhöhe: 2.750000; OKFF: 0
Gipsfaserplatten 2-lagig (BSK) | WUN-H2-E00-055 | CEILING | layer 0.036 m | 1116Dfl0000464126/01 | m² | Trockenbauarbeiten | 1 | 0.036 | 0 | 1 | Deckenfläche |  | 0 | 0 | NEW | 2.75 | AllplanAttributes - Bezeichnung: Gipsfaserplatten 2-lagig (BSK)
Gipsfaserplatten 2-lagig (BSK) | WUN-H2-E00-055 | CEILING | Installationshöhe 0.464 m | 1116Dfl0000464126/02 | m² | Trockenbauarbeiten | 2 | 0.464 | 0 | 1 | Bekleidung | Installationshöhe | 0 | 0 | NEW | 2.75 | Pset_CoveringCommon - FireRating: für korrekte FläVisu; AllplanAttributes - ash_lichte Raumhöhe: 2.750000; OKFF: 0
Gipsfaserplatten 2-lagig (BSK) | WUN-H2-E00-055 | CEILING | A1 0.15 m | 1116Dfl0000464126/03 | m² | Trockenbauarbeiten | 3 | 0.15 | 0 | 1 | Bekleidung | A1 | 0 | 0 | NEW | 2.75 | Pset_CoveringCommon - FireRating: -; AcousticRating: -; AllplanAttributes - ash_lichte Raumhöhe: 2.750000; OKFF: 0
Gipsfaserplatten 2-lagig (BSK) | WUN-H2-E00-055 | CEILING | D1 0.001 m | 1116Dfl0000464126/04 | m² | Maler- und Lackierarbeiten | 4 | 0.001 | 0 | 1 | Bekleidung | D1 | 0 | 0 | NEW | 2.75 | AllplanAttributes - ash_lichte Raumhöhe: 2.750000; OKFF: 0
Gipsfaserplatten 2-lagig (BSK) | WUN-H2-E00-055 | CEILING | layer 0.036 m | 1116Dfl0000464128/01 | m² | Trockenbauarbeiten | 1 | 0.036 | 0 | 1 | Deckenfläche |  | 0 | 0 | NEW | 2.75 | AllplanAttributes - Bezeichnung: Gipsfaserplatten 2-lagig (BSK)
Gipsfaserplatten 2-lagig (BSK) | WUN-H2-E00-055 | CEILING | Installationshöhe 0.464 m | 1116Dfl0000464128/02 | m² | Trockenbauarbeiten | 2 | 0.464 | 0 | 1 | Bekleidung | Installationshöhe | 0 | 0 | NEW | 2.75 | Pset_CoveringCommon - FireRating: für korrekte FläVisu; AllplanAttributes - ash_lichte Raumhöhe: 2.750000; OKFF: 0
Gipsfaserplatten 2-lagig (BSK) | WUN-H2-E00-055 | CEILING | Aa 0.15 m | 1116Dfl0000464128/03 | m² | Trockenbauarbeiten | 3 | 0.15 | 0 | 1 | Bekleidung | Aa | 0 | 0 | NEW | 2.75 | Pset_CoveringCommon - FireRating: -; AcousticRating: -; AllplanAttributes - ash_lichte Raumhöhe: 2.750000; OKFF: 0
Gipsfaserplatten 2-lagig (BSK) | WUN-H2-E00-055 | CEILING | D1 0.001 m | 1116Dfl0000464128/04 | m² | Maler- und Lackierarbeiten | 4 | 0.001 | 0 | 1 | Bekleidung | D1 | 0 | 0 | NEW | 2.75 | AllplanAttributes - ash_lichte Raumhöhe: 2.750000; OKFF: 0
Gipsfaserplatten 2-lagig (BSK) | WUN-H2-E00-055 | CEILING | layer 0.036 m | 1116Dfl0000065579/01 | m² | Trockenbauarbeiten | 1 | 0.036 | 0 | 1 | Deckenfläche |  | 0 | 0 | NEW | 3.1 | AllplanAttributes - Bezeichnung: Gipsfaserplatten 2-lagig (BSK)
Gipsfaserplatten 2-lagig (BSK) | WUN-H2-E00-055 | CEILING | Installationshöhe 0.164 m | 1116Dfl0000065579/02 | m² | Trockenbauarbeiten | 2 | 0.164 | 0 | 1 | Bekleidung | Installationshöhe | 0 | 0 | NEW | 3.1 | Pset_CoveringCommon - FireRating: -; AcousticRating: -; AllplanAttributes - ash_lichte Raumhöhe: 3.100000
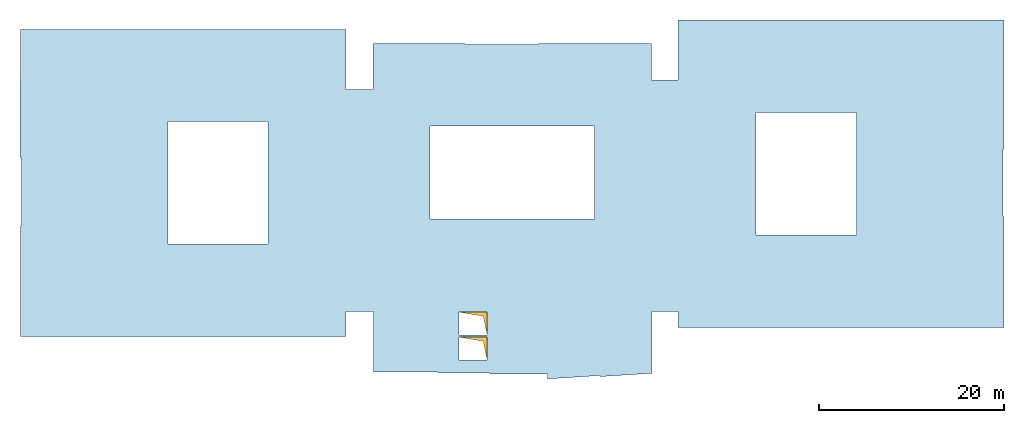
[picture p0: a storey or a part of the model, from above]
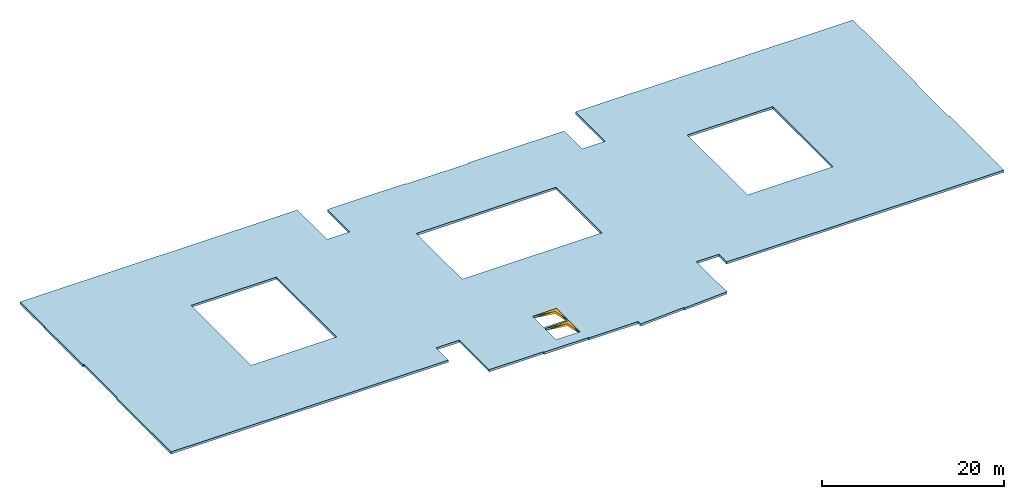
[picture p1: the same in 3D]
Properties of the parts of a building model (IFC4), part 23 of 80

# IfcCovering (3945)
Name | In | PredefinedType | Material | Allright_Bauteil_ID | Abrechnungsart | Gewerk | Schichtnummer | Schichtdicke (m) | Dicke (m) | Faktor | Objektname | AllplanAttributes, Material | Bezugshöhe | Deltahöhe | Status | D_lichte Raumhöhe [Zahl] (m)
Gipsfaserplatten 2-lagig (BSK) | WUN-H2-E00-055 | CEILING | A1 0.1 m | 1116Dfl0000065579/03 | m² | Trockenbauarbeiten | 3 | 0.1 | 0 | 1 | Bekleidung | A1 | 0 | 0 | NEW | 3.1 | Pset_CoveringCommon - FireRating: -; AcousticRating: -; AllplanAttributes - ash_lichte Raumhöhe: 3.100000
Gipsfaserplatten 2-lagig (BSK) | WUN-H2-E00-055 | CEILING | D1 0.001 m | 1116Dfl0000065579/04 | m² | Maler- und Lackierarbeiten | 4 | 0.001 | 0 | 1 | Bekleidung | D1 | 0 | 0 | NEW | 3.1 | AllplanAttributes - ash_lichte Raumhöhe: 3.100000
Gipsfaserplatten 2-lagig (BSK) | WUN-H2-E00-055 | CEILING | layer 0.036 m | 1116Dfl0000466219/01 | m² | Trockenbauarbeiten | 1 | 0.036 | 0 | 1 | Deckenfläche |  | 0 | 0 | NEW | 3.1 | AllplanAttributes - Bezeichnung: Gipsfaserplatten 2-lagig (BSK)
Gipsfaserplatten 2-lagig (BSK) | WUN-H2-E00-055 | CEILING | Installationshöhe 0.124 m | 1116Dfl0000466219/02 | m² | Trockenbauarbeiten | 2 | 0.124 | 0 | 1 | Bekleidung | Installationshöhe | 0 | 0 | NEW | 3.1 | Pset_CoveringCommon - FireRating: für korrekte FläVisu; AllplanAttributes - ash_lichte Raumhöhe: 3.100000; OKFF: 0
Gipsfaserplatten 2-lagig (BSK) | WUN-H2-E00-055 | CEILING | A1 0.1 m | 1116Dfl0000466219/03 | m² | Trockenbauarbeiten | 3 | 0.1 | 0 | 1 | Bekleidung | A1 | 0 | 0 | NEW | 3.1 | Pset_CoveringCommon - FireRating: -; AcousticRating: -; AllplanAttributes - ash_lichte Raumhöhe: 3.100000; OKFF: 0
Gipsfaserplatten 2-lagig (BSK) | WUN-H2-E00-055 | CEILING | D1 0.001 m | 1116Dfl0000466219/04 | m² | Maler- und Lackierarbeiten | 4 | 0.001 | 0 | 1 | Bekleidung | D1 | 0 | 0 | NEW | 3.1 | AllplanAttributes - ash_lichte Raumhöhe: 3.100000; OKFF: 0
Gipsfaserplatten 2-lagig (BSK) | WUN-H2-E00-027 | CEILING | C/C 0.036 m | 1116Dfl0000065321/01 | m² | Trockenbauarbeiten | 1 | 0.036 | 0 | 1 | Deckenfläche | C/C | 0 | 0 | NEW | 3.364 | AllplanAttributes - Bezeichnung: Gipsfaserplatten 2-lagig (BSK)
Gipsfaserplatten 2-lagig (BSK) | WUN-H2-E00-027 | CEILING | D4 0.001 m | 1116Dfl0000065321/02 | m² | Maler- und Lackierarbeiten | 2 | 0.001 | 0 | 1 | Deckenfläche | D4 | 0 | 0 | NEW
PVC | WUN-H2-E00-027 | FLOORING | Ku3 0.2 m | 1116Bfl0000065320/01 | m² | Bodenbelagsarbeiten | 1 | 0.2 | 0 | 1 | Bodenfläche | Ku3 | 0 | 0 | NEW | AllplanAttributes - Bezeichnung: PVC; Raumnr. Bauherr: 2.11_A2_02; ash B_Aufbau: B1; ash B_Rutschhemmung: R9
Gipsfaserplatten 2-lagig (BSK) | WUN-H2-E00-028 | CEILING | C/C 0.036 m | 1116Dfl0000065319/01 | m² | Trockenbauarbeiten | 1 | 0.036 | 0 | 1 | Deckenfläche | C/C | 0 | 0 | NEW | 3.364 | AllplanAttributes - Bezeichnung: Gipsfaserplatten 2-lagig (BSK)
Gipsfaserplatten 2-lagig (BSK) | WUN-H2-E00-028 | CEILING | D4 0.001 m | 1116Dfl0000065319/02 | m² | Maler- und Lackierarbeiten | 2 | 0.001 | 0 | 1 | Deckenfläche | D4 | 0 | 0 | NEW
PVC | WUN-H2-E00-028 | FLOORING | Ku3 0.2 m | 1116Bfl0000065318/01 | m² | Bodenbelagsarbeiten | 1 | 0.2 | 0 | 1 | Bodenfläche | Ku3 | 0 | 0 | NEW | AllplanAttributes - Bezeichnung: PVC; Raumnr. Bauherr: 2.11_A2_02; ash B_Aufbau: B1; ash B_Rutschhemmung: R9
Gipsfaserplatten 2-lagig (BSK) | WUN-H2-E00-088 | CEILING | C/C 0.036 m | 1116Dfl0000065414/01 | m² | Trockenbauarbeiten | 1 | 0.036 | 0 | 1 | Deckenfläche | C/C | 0 | 0 | NEW | 3.364 | AllplanAttributes - Bezeichnung: Gipsfaserplatten 2-lagig (BSK)
Gipsfaserplatten 2-lagig (BSK) | WUN-H2-E00-088 | CEILING | D4 0.001 m | 1116Dfl0000065414/02 | m² | Maler- und Lackierarbeiten | 2 | 0.001 | 0 | 1 | Deckenfläche | D4 | 0 | 0 | NEW
PVC | WUN-H2-E00-088 | FLOORING | Ku3 0.2 m | 1116Bfl0000065413/01 | m² | Bodenbelagsarbeiten | 1 | 0.2 | 0 | 1 | Bodenfläche | Ku3 | 0 | 0 | NEW | AllplanAttributes - Bezeichnung: PVC; Raumnr. Bauherr: 2.11_A2_02; ash B_Aufbau: B1; ash B_Rutschhemmung: R9
Gipsfaserplatten 2-lagig (BSK) | WUN-H2-E00-087 | CEILING | C/C 0.036 m | 1116Dfl0000065417/01 | m² | Trockenbauarbeiten | 1 | 0.036 | 0 | 1 | Deckenfläche | C/C | 0 | 0 | NEW | 3.364 | AllplanAttributes - Bezeichnung: Gipsfaserplatten 2-lagig (BSK)
Gipsfaserplatten 2-lagig (BSK) | WUN-H2-E00-087 | CEILING | D4 0.001 m | 1116Dfl0000065417/02 | m² | Maler- und Lackierarbeiten | 2 | 0.001 | 0 | 1 | Deckenfläche | D4 | 0 | 0 | NEW
PVC | WUN-H2-E00-087 | FLOORING | Ku3 0.2 m | 1116Bfl0000065416/01 | m² | Bodenbelagsarbeiten | 1 | 0.2 | 0 | 1 | Bodenfläche | Ku3 | 0 | 0 | NEW | AllplanAttributes - Bezeichnung: PVC; Raumnr. Bauherr: 2.11_A2_02; ash B_Aufbau: B1; ash B_Rutschhemmung: R9
Gipsfaserplatten 2-lagig (BSK) | WUN-H2-E00-054 | CEILING | C/C 0.036 m | 1116Dfl0000065330/01 | m² | Trockenbauarbeiten | 1 | 0.036 | 0 | 1 | Deckenfläche | C/C | 0 | 0 | NEW | 3.364 | AllplanAttributes - Bezeichnung: Gipsfaserplatten 2-lagig (BSK)
Gipsfaserplatten 2-lagig (BSK) | WUN-H2-E00-054 | CEILING | D4 0.001 m | 1116Dfl0000065330/02 | m² | Maler- und Lackierarbeiten | 2 | 0.001 | 0 | 1 | Deckenfläche | D4 | 0 | 0 | NEW
PVC | WUN-H2-E00-054 | FLOORING | Ku3 0.2 m | 1116Bfl0000065331/01 | m² | Bodenbelagsarbeiten | 1 | 0.2 | 0 | 1 | Bodenfläche | Ku3 | 0 | 0 | NEW | AllplanAttributes - Bezeichnung: PVC; Raumnr. Bauherr: 2.11_A2_02; ash B_Aufbau: B1; ash B_Rutschhemmung: R9
Gipsfaserplatten 2-lagig (BSK) | WUN-H2-E00-053 | CEILING | C/C 0.036 m | 1116Dfl0000065328/01 | m² | Trockenbauarbeiten | 1 | 0.036 | 0 | 1 | Deckenfläche | C/C | 0 | 0 | NEW | 3.364 | AllplanAttributes - Bezeichnung: Gipsfaserplatten 2-lagig (BSK)
Gipsfaserplatten 2-lagig (BSK) | WUN-H2-E00-053 | CEILING | D4 0.001 m | 1116Dfl0000065328/02 | m² | Maler- und Lackierarbeiten | 2 | 0.001 | 0 | 1 | Deckenfläche | D4 | 0 | 0 | NEW
PVC | WUN-H2-E00-053 | FLOORING | Ku3 0.2 m | 1116Bfl0000065329/01 | m² | Bodenbelagsarbeiten | 1 | 0.2 | 0 | 1 | Bodenfläche | Ku3 | 0 | 0 | NEW | AllplanAttributes - Bezeichnung: PVC; Raumnr. Bauherr: 2.11_A2_02; ash B_Aufbau: B1; ash B_Rutschhemmung: R9
Ink . Installationsbau 50cm | WUN-H2-E00-S01 | FLOORING | Gitterrost 0.6 m | 1116Bfl0000878141/01 | m² | Bodenbelagsarbeiten | 1 | 0.6 | 0 | 1 | Bodenfläche | Gitterrost | 0 | 0 | NEW | AllplanAttributes - Bezeichnung: Ink . Installationsbau 50cm; Raumnr. Bauherr: 2.11_A2_02
Gitterrost Treppenstufe | WUN-H2-E00-S01 | FLOORING | Gitterrost 0.1 m | 1116Bfl0000880498/01 | m² | Bodenbelagsarbeiten | 1 | 0.1 | 0 | 1 | Bodenfläche | Gitterrost | 0 | 0 | NEW | AllplanAttributes - Bezeichnung: Gitterrost Treppenstufe; Raumnr. Bauherr: 2.11_A2_02
Ink . Installationsbau 10cm | WUN-H2-E00-S01 | FLOORING | Gitterrost 0.2 m | 1116Bfl0000880563/01 | m² | Bodenbelagsarbeiten | 1 | 0.2 | 0 | 1 | Bodenfläche | Gitterrost | 0 | 0 | NEW | AllplanAttributes - Bezeichnung: Ink . Installationsbau 10cm; Raumnr. Bauherr: 2.11_A2_02
Gipsfaserplatten 2-lagig (BSK) | WUN-H2-E00-S01 | CEILING | C/C 0.036 m | 1116Dfl0000065613/01 | m² | Trockenbauarbeiten | 1 | 0.036 | 0 | 1 | Deckenfläche | C/C | 0 | 0 | NEW | 3.364 | AllplanAttributes - Bezeichnung: Gipsfaserplatten 2-lagig (BSK)
Gipsfaserplatten 2-lagig (BSK) | WUN-H2-E00-S01 | CEILING | D4 0.001 m | 1116Dfl0000065613/02 | m² | Maler- und Lackierarbeiten | 2 | 0.001 | 0 | 1 | Deckenfläche | D4 | 0 | 0 | NEW

# IfcDoor (58)
PredefinedType: DOOR; OperationType: USERDEFINED
AllplanQuantities - HeightWindowSillOutside: 0; HeightWindowSillInside: 0; OffsetOpeningTop: 0; OffsetOpeningLeft: 0; OffsetOpeningRight: 0
Name | In | OverallHeight (m) | OverallWidth (m) | Material | GlassSurface | OffsetOpeningBottom | DeductionOpeningBottom | DeductionOpeningLeft = DeductionOpeningRight | DeductionOpeningTop | Status | IsExternal | FireRating | ThermalTransmittance (W/K/m2) | HandicapAccessible | SmokeStop = SelfClosing | FireExit | SecurityRating | AllplanAttributes (SMT), Gewerk | AllplanAttributes (SMT), V6 (m) = AllplanAttributes (SMT), V7 (m) = AllplanAttributes (SMT), V8 (m) = AllplanAttributes (SMT), V9 = AllplanAttributes (SMT), ash T_Lüftungsgitter (m2) = AllplanAttributes (SMT), ash T_Anz_Reedkontakte | AllplanAttributes (SMT), Ortscode_Geschoßbezeichnung | AllplanAttributes (SMT), Programmversion | AllplanAttributes (SMT), Objektname | AllplanAttributes (SMT), Bezeichnung | AllplanAttributes (SMT), Material | AllplanAttributes (SMT), Plugin_Bezeichnung | AllplanAttributes (SMT), Plugin_Objektname | AllplanAttributes (SMT), Glasanteil_berücksichtigen | AllplanAttributes (SMT), Version | AllplanAttributes (SMT), ash T_Sichtschutz = AllplanAttributes (SMT), ash R_Verweis Wandansicht = AllplanAttributes (SMT), ash T_Gewerk Los = AllplanAttributes (SMT), ash T_Standflügel-Betätigung = AllplanAttributes (SMT), ash T_Zusatzfunktion Türschließer = AllplanAttributes (SMT), ash T_Türschließer-Montage = AllplanAttributes (SMT), ash T_Zusätzliche Rauchmelder = AllplanAttributes (SMT), ash T_Zusätzl. Anschluss an BMA = AllplanAttributes (SMT), ash T_Impulsgeber = AllplanAttributes (SMT), ash T_Sicherheits-Sensorleisten = AllplanAttributes (SMT), ash T_Anschl. an Einbruchmeld.anl. = AllplanAttributes (SMT), ash T_Klemmschutz = AllplanAttributes (SMT), ash T_LV-Positions-Nr. = AllplanAttributes (SMT), ash T_Plan-Nr. = AllplanAttributes (SMT), ash T_Sonstiges, Bemerkungen = AllplanAttributes (SMT), ash T_Bodentürstopper = AllplanAttributes (SMT), ash T_Material Seitenteil = AllplanAttributes (SMT), ash T_Kantengeometrie = AllplanAttributes (SMT), ash T_Kantenmaterial = AllplanAttributes (SMT), ash T_Feuchtebeständigkeit = AllplanAttributes (SMT), ash T_Glasausschnitt = AllplanAttributes (SMT), ash T_Sonder_Wandmaterial = AllplanAttributes (SMT), ash T_Bodeneinstand = AllplanAttributes (SMT), ash T_Blatt_Farbe | AllplanAttributes (SMT), ash T_Panik | AllplanAttributes (SMT), ash T_Zarge_Typ | AllplanAttributes (SMT), ash T_Türschließer | AllplanAttributes (SMT), ash T_Erforderl. Durchgangsbreite (m) | AllplanAttributes (SMT), ash T_Türblatt sichtbar 2D | AllplanAttributes (SMT), ash T_Zusatzfunktion Panikschloss | AllplanAttributes (SMT), ash T_Fluchtwegsicherung | AllplanAttributes (SMT), ash T_Feststellanlage (FSA) | AllplanAttributes (SMT), ash T_Anschl. an Zuttrittskontrolle | AllplanAttributes (SMT), OKFF | AllplanAttributes (SMT), ash T_Strahlenschutz | AllplanAttributes (SMT), ash T_Tür-Nr. | AllplanAttributes (SMT), ash T_Blatt_Oberfläche | AllplanAttributes (SMT), ash T_Erford. Durgangshöhe (m) | AllplanAttributes (SMT), ash T_Rammschutz | AllplanAttributes (SMT), ash T_Fluchtwegrichtung | AllplanAttributes (SMT), ash T_Anschlag Gangflügel | AllplanAttributes (SMT), ash T_Bodendichtung | AllplanAttributes (SMT), ash T_E_Öffner | AllplanAttributes (SMT), ash T_Automatik_Antrieb | AllplanAttributes (SMT), ash T_Sturz | AllplanAttributes (SMT), ash T_Blatt_Material | AllplanAttributes (SMT), ash T_Schlossfunktion | AllplanAttributes (SMT), ash T_Schliesszylinder | AllplanAttributes (SMT), ash T_Beschlag | AllplanAttributes (SMT), ash T_Anz_Riegelkontakte | AllplanAttributes (SMT), ash T_Schallschutz | AllplanAttributes (SMT), ash T_Zarge_Material | AllplanAttributes (SMT), ash T_Raum zugehörigkeit | AllplanAttributes (SMT), Attributset-Objekt | AllplanAttributes (SMT), P_ID | AllplanAttributes (SMT), Allright_Bauteil_ID | AllplanAttributes (SMT), Abrechnungsart | AllplanAttributes (SMT), Text1 | AllplanAttributes (SMT), ash T_Zulage Schachttür = AllplanAttributes (SMT), ash T_Dichtschließend = AllplanAttributes (SMT), ash T_nicht abschließbar | AllplanAttributes (SMT), ash T_Laserschutz | Text4 | ash T_Steuerung (BS) | AllplanAttributes (TGR 1.5), Codetext | AllplanAttributes (TGR 1.5), V6 (m) = AllplanAttributes (TGR 1.5), V7 (m) = AllplanAttributes (TGR 1.5), V8 (m) = AllplanAttributes (TGR 1.5), V9 | AllplanAttributes (TGR 1.5), Programmversion | AllplanAttributes (TGR 1.5), Objektname | AllplanAttributes (TGR 1.5), Text1 | AllplanAttributes (TGR 1.5), Bezeichnung | AllplanAttributes (TGR 1.5), Plugin_Bezeichnung | AllplanAttributes (TGR 1.5), Plugin_Objektname | AllplanAttributes (TGR 1.5), Gesamtlänge | AllplanAttributes (TGR 1.5), Version | AllplanAttributes (TGR 1.5), ash T_Türprofilnummer | AllplanAttributes (TGR 1.5), P_ID | AllplanAttributes (TGR 1.5), Allright_Bauteil_ID | AllplanAttributes (TGR 1.5), Abrechnungsart | AllplanAttributes (SMT), Positionsnummer_Text
FS-Vorhang | H2 Ebene +3 | 2.49 | 1.84 | TI-1F-UZ-M-ZK | 0 | 200 | 200 | 120 | 0 | NEW | no | EW 60 | 0 | no | yes | no | - | AllplanAttributes (FS-Vorhang) - Gewerk: Zimmer- und Holzbauarbeiten; V6: 0 m; V7: 0 m; V8: 0 m; V9: 0; Ortscode_Geschoßbezeichnung: E00; Programmversion: 3.1; Objektname: Brandschutzvorhang; Text1: S200 C2; Bezeichnung: FS-Vorhang; Material: TI-1F-UZ-M-ZK; Plugin_Bezeichnung: MainObject; Plugin_Objektname: SmartPartCompressed; Glasanteil_berücksichtigen: 100; Version: 7.21; ash T_Sichtschutz: -; ash R_Verweis Wandansicht: -; ash T_Zulage Schachttür: no; ash T_Dichtschließend: no; ash T_Panik: -; ash T_Zarge_Typ: U; ash T_Türschließer: -; ash T_Gewerk Los: -; ash T_Erforderl. Durchgangsbreite: 0 m; ash T_Türblatt sichtbar 2D: ja; ash T_Zusatzfunktion Panikschloss: -; ash T_Fluchtwegsicherung: -; ash T_Standflügel-Betätigung: -; ash T_Zusatzfunktion Türschließer: -; ash T_Türschließer-Montage: -; ash T_Feststellanlage (FSA): -; ash T_Zusätzliche Rauchmelder: -; ash T_Zusätzl. Anschluss an BMA: -; ash T_Impulsgeber: -; ash T_Sicherheits-Sensorleisten: -; ash T_Anschl. an Zuttrittskontrolle: -; ash T_Anschl. an Einbruchmeld.anl.: -; ash T_Klemmschutz: -; ash T_LV-Positions-Nr.: -; ash T_Plan-Nr.: -; ash T_Sonstiges, Bemerkungen: -; OKFF: 0; ash T_Bodentürstopper: -; ash T_nicht abschließbar: no; ash T_Material Seitenteil: -; ash T_Strahlenschutz: 0.000000; ash T_Tür-Nr.: FS-Vorhang; ash T_Kantengeometrie: -; ash T_Kantenmaterial: -; ash T_Blatt_Oberfläche: L; ash T_Erford. Durgangshöhe: 0 m; ash T_Laserschutz: -; ash T_Rammschutz: -; ash T_Fluchtwegrichtung: -; ash T_Anschlag Gangflügel: -; ash T_Bodendichtung: -; ash T_Lüftungsgitter: 0 m2; ash T_Feuchtebeständigkeit: -; ash T_E_Öffner: -; ash T_Automatik_Antrieb: -; ash T_Sturz: -; ash T_Blatt_Material: AL; ash T_Schlossfunktion: -; ash T_Schliesszylinder: -; ash T_Beschlag: -; ash T_Material Oberlicht: -; ash T_Glasausschnitt: -; ash T_Sonder_Wandmaterial: -; ash T_Anz_Reedkontakte: 0; ash T_Anz_Riegelkontakte: 0; ash T_Schallschutz: -; ash T_Zarge_Material: S; ash T_Bodeneinstand: -; ash T_Raum zugehörigkeit: BS; ash T_Blatt_Farbe: -; Attributset-Objekt: Door; P_ID: 1115Rau0000005163; Allright_Bauteil_ID: 1263Mak0812964154; Abrechnungsart: St
SMT | H2 Ebene +2 | 2.7 | 2.019 | TA-1F-AG-D-2S-O | 3.5701 | 150 | 0 | 50 | 50 | NEW | yes | 0 | 1 |  |  |  | RC 1 | Metallbau-, Schlosserarbeiten | 0 | E01 | 3.1 | Türmakro | SMT | TA-1F-AG-D-2S-O | MainObject | SmartPartCompressed | 100 | 7.21 | - | - | - | - | 1.05 | ja | - | - | - | - | 7.5 | 0.000000 | TA-1FL-D-1S-E02-014 | - | 2.05 | - | - | - | - | - | - | - | - | - | - | - | 0 | - | - | BS | Door | 1215Rau0000006920 | 1205Mak0000281336 | St | AllplanAttributes (SMT) - ash T_Unterschnitt: -; ash T_Material Oberlicht: -; ash D_Detailverweis: <undefiniert>; Sonnenschutztyp: Movable; g-Wert: 0,51; Pset_DoorCommon - AcousticRating: 32; Reference: T_Typ11
SMT | H2 Ebene +2 | 2.7 | 2.013 | TA-1F-AG-D-2S-O | 3.5563 | 150 | 0 | 50 | 50 | NEW | yes | 0 | 1 |  |  |  | RC 1 | Metallbau-, Schlosserarbeiten | 0 | E01 | 3.1 | Türmakro | SMT | TA-1F-AG-D-2S-O | MainObject | SmartPartCompressed | 100 | 7.21 | - | - | - | - | 1.05 | ja | - | - | - | - | 7.5 | 0.000000 | TA-1FR-D-1S-E02-015 | - | 2.05 | - | - | - | - | - | - | - | - | - | - | - | 0 | - | - | BS | Door | 1215Rau0000006941 | 1205Mak0000281687 | St | AllplanAttributes (SMT) - ash T_Unterschnitt: -; ash T_Material Oberlicht: -; ash D_Detailverweis: <undefiniert>; Sonnenschutztyp: Movable; g-Wert: 0,51; Pset_DoorCommon - AcousticRating: 32; Reference: T_Typ12
SMT | H2 Ebene +2 | 2.41 | 3.668 | TI-1F-AG-S | 6.75221 | 150 | 150 | 50 | 50 | NEW | no |  | 0 | no | no | no |  | Metallbau-, Schlosserarbeiten | 0 | E02 | 3.1 | Türmakro | SMT | TI-1F-AG-S | MainObject | SmartPartCompressed | 100 | 7.21 | - | - | - | - | 0 | ja | - | - | - |  | 7.5 | 0.000000 | E00-050-002-92 | L | 0 | - | - | - | - | - | - | - | SG | - | PZ | DD | 0 | - | - | BS | Door | 1216Rau0000047209 | 1213Mak0813562514 | St | 92 | no | - | AllplanAttributes (SMT) - ash T_Unterschnitt: 1; AllplanAttributes (TGR 1.6) - Codetext: Typ; V6: 0 m; V7: 0 m; V8: 0 m; V9: 0; Ortscode_Geschoßbezeichnung: E02; Programmversion: 3.1; Objektname: TGR-Makro; Text1: PlanNo.; Bezeichnung: TGR 1.6; Plugin_Bezeichnung: MainObject; Plugin_Objektname: SmartPartCompressed; Gesamtlänge: 10.768; Version: 1.6; OKFF: 7.5; ash T_Türprofilnummer: 2; Allright_Bauteil_ID: 1213Mak0813242652; Abrechnungsart: St
SMT | H2 Ebene +2 | 2.41 | 1.355 | TI-1F-AG-D | 2.0493 | 150 | 100 | 0 | 0 | NEW | no | EI2 30 | 0 | no | yes | no |  | Zimmer- und Holzbauarbeiten | 0 | E02 | 3.1 | Türmakro | SMT | TI-1F-AG-D | MainObject | SmartPartCompressed | 100 | 7.21 | - | - | BZ | OTS | 0 | ja | - | - | EMF | - | 7.5 | 0.000000 | E02-013-001-165 | L | 0 | - | - | - | Ja |  | - | S | S | E | PZ | DD | 1 | - | - | BS | Door | 1216Rau0000046628 | 1213Mak0813203591 | St | 165 | no | - | Stahl-Glas-Tür | E | Typ | 0 | 3.1 | TGR-Makro | PlanNo. | TGR 1.5 | MainObject | SmartPartCompressed | 8.51 | 1.5 | 2 | 1215Rau0000006941 | 1213Mak0813222507 | St | AllplanAttributes (TGR 1.5) - Ortscode_Geschoßbezeichnung: E02; OKFF: 7.5
SMT | H2 Ebene +2 | 2.41 | 3.61 | TI-1F-AG-S | 6.63447 | 150 | 150 | 50 | 50 | NEW | no |  | 0 | no | no | no |  | Metallbau-, Schlosserarbeiten | 0 | E02 | 3.1 | Türmakro | SMT | TI-1F-AG-S | MainObject | SmartPartCompressed | 100 | 7.21 | - | - | - | - | 0 | ja | - | - | - | - | 7.5 |  | E02-008-002-85 | - | 0 | BL | - | - | - | - | - | - | - | - | PZ | DD | 0 | - | - | BS | Door | 1216Rau0000046485 | 1213Mak0813562753 | St | 85 | no | AllplanAttributes (SMT) - ash T_Unterschnitt: 0,4; AllplanAttributes (TGR 1.6) - Codetext: Typ; V6: 0 m; V7: 0 m; V8: 0 m; V9: 0; Ortscode_Geschoßbezeichnung: E02; Programmversion: 3.1; Objektname: TGR-Makro; Text1: PlanNo.; Bezeichnung: TGR 1.6; Plugin_Bezeichnung: MainObject; Plugin_Objektname: SmartPartCompressed; Gesamtlänge: 10.71; Version: 1.6; OKFF: 7.5; ash T_Türprofilnummer: 2; Allright_Bauteil_ID: 1213Mak0813242885; Abrechnungsart: St
SMT | H2 Ebene +2 | 2.53 | 2.3 | TI-1F-AG-D-1S-O | 4.00309 | 150 | 100 | 0 | 0 | NEW | no | EI2 30 | 0 | no | yes | no |  | Zimmer- und Holzbauarbeiten | 0 | E02 | 3.1 | Türmakro | SMT | TI-1F-AG-D-1S-O | MainObject | SmartPartCompressed | 100 | 7.21 | - | N | BZ | OTS | 0 | ja | - | FWS | - | ZK | 7.5 | 0.000000 | E02-T03-001-88 | L | 0 | SB | A | - | - | TÖ + FTÖ | - |  | S | E | PZ(v) | KD | 1 | - | - | BS | Door | 1215Rau0000006923 | 1213Mak0813004828 | St | 88 | no | - | Stahl-Glas-Tür | E, H | AllplanAttributes (SMT) - Text2: X; ash T_Steuerung (BG): E, H
SMT | H2 Ebene +2 | 2.41 | 1.325 | TI-1F-AG-D | 1.9899 | 150 | 100 | 0 | 0 | NEW | no | EI2 60 | 0 | no | yes | no |  | Zimmer- und Holzbauarbeiten | 0 | E02 | 3.1 | Türmakro, -SmartPart | SMT | TI-1F-AG-D | MainObject | SmartPartCompressed | 100 | 7.21 | - | - | BZ | OTS | 0 | ja | - | - | EMF | - | 7.5 | 0.000000 | E02-063-001-158 | L | 0 | - | - | - | Ja |  | - | S | S | E | PZ | DD | 1 | - | - | BS | Door | 1216Rau0000046869 | 1213Mak0813186182 | St | 158 | no |  | Stahl-Glas-Tür | E | Typ | 0 | 3.1 | TGR-Makro | PlanNo. | TGR 1.5 | MainObject | SmartPartCompressed | 8.48 | 1.5 | 2 | 1216Rau0000046869 | 1213Mak0813204276 | St | AllplanAttributes (TGR 1.5) - Ortscode_Geschoßbezeichnung: E02; OKFF: 7.5
SMT | H2 Ebene +2 | 2.41 | 1.9713 | TI-2F-AG-D-O | 3.20922 | 150 | 200 | 100 | 100 | NEW | no | EI2 30 | 0 | no | yes | no |  | Betonarbeiten | 0 | E02 | 3.1 | Türmakro, -SmartPart | SMT | TI-2F-AG-D-O | MainObject | SmartPartCompressed | 100 | 7.21 | - | N | BZ | OTS | 0 | ja | - | FWS | EMF | - | 7.5 | 0.000000 | E02-F03-002-22 | L | 0 | SB | A | - | - |  | - | S | S | E | PZ(v) | KD | 1 | - | - |  | Door | 1215Rau0000006920 | 1213Mak0813461435 | St | 22 | no | - | Stahl-Glas-Tür | (B), E, H | Typ | 0 | 3.1 | TGR-Makro | PlanNo. | TGR 1.5 | MainObject | SmartPartCompressed | 9.1263 | 1.5 | 2 | 1215Rau0000006941 | 1213Mak0813222362 | St | Pset_DoorCommon - AcousticRating: 0; Reference: Codetext; AllplanAttributes (TGR 1.5) - Ortscode_Geschoßbezeichnung: E02; OKFF: 7.5; AllplanAttributes (SMT) - Text2: -; ash T_Steuerung (BG): E, H; Codetext: Codetext; Funktion: Flurtür; Tragendes Bauteil: yes; Typ: 0; Brennbares Material: no; Brandverhalten: 0; Brandabschnittsdefinierendes Bauteil: no; Brandschutzklasse: A
SMT | H2 Ebene +2 | 2.41 | 1.965 | TI-2F-AG-D-O | 3.19605 | 150 | 200 | 100 | 100 | NEW | no | EI2 30 | 0 | no | yes | no |  | Betonarbeiten | 0 | E02 | 3.1 | Türmakro, -SmartPart | SMT | TI-2F-AG-D-O | MainObject | SmartPartCompressed | 100 | 7.21 | - | N | BZ | OTS | 0 | ja | - | FWS | EMF | - | 7.5 |  | E02-F07-001-153 | L | 0 | SB | A | - | - |  | - | S | S | E | PZ(v) | KD | 1 |  | - |  | Door | 1215Rau0000006941 | 1213Mak0813460959 | St | 153 | no |  | Stahl-Glas-Tür | (B), E, H | Typ | 0 | 3.1 | TGR-Makro | PlanNo. | TGR 1.5 | MainObject | SmartPartCompressed | 9.12 | 1.5 | 2 | 1215Rau0000006941 | 1213Mak0813217679 | St | Pset_DoorCommon - AcousticRating: 0; Reference: Codetext; AllplanAttributes (TGR 1.5) - Ortscode_Geschoßbezeichnung: E02; OKFF: 7.5; AllplanAttributes (SMT) - Text2: -; ash T_Steuerung (BG): E, H; Codetext: Codetext; Funktion: Flurtür; Tragendes Bauteil: yes; Typ: 0; Brennbares Material: no; Brandverhalten: 0; Brandabschnittsdefinierendes Bauteil: no; Brandschutzklasse: A
SMT | H2 Ebene +2 | 2.41 | 1.968 | TI-2F-AG-D-O | 3.20232 | 150 | 200 | 100 | 100 | NEW | no | EI2 30 | 0 | no | yes | no |  | Zimmer- und Holzbauarbeiten | 0 | E02 | 3.0 | Türmakro | SMT | TI-2F-AG-D-O | MainObject | SmartPartCompressed | 100 | 8.11 | - | N | BZ | OTS | 0 | ja |  | FWS | EMF | ZK | 7.5 | 0.000000 | E02-F08-004-94a | L | 0 | SB | A | - | - | TÖ + FTÖ | - | S | S | E | PZ(v) | KD | 1 | - | - | BS | Door | 1215Rau0000006905 | 1213Mak0813531380 | St | 94a | no | - | Stahl-Glas-Tür | B, E, H | Typ | 0 | 3.1 | TGR-Makro | PlanNo. | TGR 1.5 | MainObject | SmartPartCompressed | 9.123 | 1.5 | 2 | 1215Rau0000006905 | 1213Mak0813218743 | St | AllplanAttributes (TGR 1.5) - Ortscode_Geschoßbezeichnung: E02; OKFF: 7.5; AllplanAttributes (SMT) - Text2: X; ash T_Steuerung (BG): E, H
SMT | H2 Ebene +2 | 2.41 | 1.9715 | TI-2F-AG-D-O | 3.20964 | 150 | 200 | 100 | 100 |  |  | EI2 30 | 0 | no | yes | no |  |  | 0 | E02 | 3.1 | Türmakro, -SmartPart | SMT | TI-2F-AG-D-O | MainObject | SmartPartCompressed | 100 | 7.21 | - | - | BZ | OTS | 0 | ja | - | FWS | EMF | - | 7.5 |  | E02-F07-001-105 | L | 0 | SB | A | - | - |  | - | S | S | E | PZ(v) | KD | 1 |  | - |  | Door | 1215Rau0000006941 | 1213Mak0813460312 | St | 105 | no |  | Stahl-Glas-Tür | (B), E, H | Typ | 0 | 3.1 | TGR-Makro | PlanNo. | TGR 1.5 | MainObject | SmartPartCompressed | 9.1265 | 1.5 | 2 | 1215Rau0000006905 | 1213Mak0813218474 | St | AllplanAttributes (TGR 1.5) - Ortscode_Geschoßbezeichnung: E02; OKFF: 7.5; AllplanAttributes (SMT) - Text2: -; ash T_Steuerung (BG): E, H
SMT | H2 Ebene +2 | 2.41 | 2.0585 | TI-2F-AG-D-O | 3.39147 | 150 | 200 | 100 | 100 | NEW | no | EI2 30 | 0 | no | yes | no | SA | Zimmer- und Holzbauarbeiten | 0 | E02 | 3.0 | Türmakro | SMT | TI-2F-AG-D-O | MainObject | SmartPartCompressed | 100 | 8.11 | - | N | BZ | OTS | 0 | ja | - | FWS | EMF | ZK | 7.5 | 0.000000 | E02-F08-003-94 | L | 0 | SB | A | - | - | TÖ + FTÖ | - | S | S | E | PZ(v) | KD | 1 | - | - | BS | Door | 1215Rau0000006905 | 1213Mak0813493992 | St | 94 | no | - | Stahl-Glas-Tür | B, E, H | Typ | 0 | 3.1 | TGR-Makro | PlanNo. | TGR 1.5 | MainObject | SmartPartCompressed | 9.2135 | 1.5 | 8 | 1215Rau0000006905 | 1213Mak0813456484 | St | AllplanAttributes (SMT) - ash D_Detailverweis: D1; Text2: X; ash T_Steuerung (BG): E, H; ash D_Plannummer: 1684; AllplanAttributes (TGR 1.5) - Ortscode_Geschoßbezeichnung: E02; OKFF: 7.5
SMT | H2 Ebene +2 | 2.41 | 2.55 | TI-1F-AG-D-1S-O | 4.08729 | 150 | 0 | 50 | 50 |  |  | EI2 60 | 0 | no | yes | no |  | Zimmer- und Holzbauarbeiten | 0 | E02 | 3.0 | Türmakro, -SmartPart | SMT | TI-1F-AG-D-1S-O | MainObject | SmartPartCompressed | 100 | 8.11 | - | - | BZ | OTS | 0 | ja | - | - | - | - | 7.5 |  | E00-008-001-80 | L | 0 | SB | - | - | - | - | - | S | S | - | PZ | DD | 0 |  | - | BS | Door | 1216Rau0000046485 | 1213Mak0813533155 | St | 80 | no |  | Stahl-Glas-Tür |  | Typ | 0 | 3.1 | TGR-Makro | PlanNo. | TGR 1.5 | MainObject | SmartPartCompressed | 9.705 | 1.5 | 8 | 1215Rau0000006905 | 1213Mak0813567694 | St | AllplanAttributes (TGR 1.5) - Ortscode_Geschoßbezeichnung: E02; OKFF: 7.5
SMT | H2 Ebene +2 | 2.41 | 1.9425 | TI-2F-AG-D-O | 3.14902 | 150 | 200 | 100 | 100 | NEW | no | EI2 30 | 0 | no | yes | no |  | Zimmer- und Holzbauarbeiten | 0 | E02 | 3.1 | Türmakro, -SmartPart | SMT | TI-2F-AG-D-O | MainObject | SmartPartCompressed | 100 | 7.21 | - | N | BZ | - | 0 | ja |  | FWS | - | ZK | 7.5 | 0.000000 | E02-F07-001-162 | L | 0 | SB | A | - | - | TÖ + FTÖ | M1 | S | S | E | PZ(v) | KD | 1 | - | - |  | Door | 1215Rau0000006941 | 1213Mak0813494960 | St | 162 | no | - | Stahl-Glas-Tür | E, G, H | Typ | 0 | 3.1 | TGR-Makro | PlanNo. | TGR 1.5 | MainObject | SmartPartCompressed | 9.0975 | 1.5 | 6 | 1215Rau0000006941 | 1213Mak0813190535 | St | Pset_DoorCommon - AcousticRating: 0; Reference: Codetext; AllplanAttributes (TGR 1.5) - Ortscode_Geschoßbezeichnung: E02; OKFF: 7.5; AllplanAttributes (SMT) - Text2: X; ash T_Steuerung (BG): B, C, E, H; Codetext: Codetext; Funktion: Flurtür; Tragendes Bauteil: yes; Typ: 0; Brennbares Material: no; Brandverhalten: 0; Brandabschnittsdefinierendes Bauteil: no; Brandschutzklasse: A
SMT | H2 Ebene +2 | 2.41 | 2.55 | TI-1F-AG-D-1S-O | 4.19889 | 150 | 0 | 50 | 50 | NEW | no | EI2 30 | 0 | no | yes | no |  | Zimmer- und Holzbauarbeiten | 0 | E02 | 3.0 | Türmakro | SMT | TI-1F-AG-D-1S-O | MainObject | SmartPartCompressed | 100 | 8.11 | - | - | BZ | OTS | 0 | ja | - | - | - |  | 7.5 |  | E02-055-001-95 | L | 0 | SB | - |  | - | - | - | S | S | - | PZ | DD | 0 | - | - | BS | Door | 1216Rau0000047209 | 1213Mak0813567758 | St | 95 | no |  | Stahl-Glas-Tür |  | Typ | 0 | 3.1 | TGR-Makro | PlanNo. | TGR 1.5 | MainObject | SmartPartCompressed | 9.705 | 1.5 | 6 | 1215Rau0000006905 | 1213Mak0813532155 | St | AllplanAttributes (TGR 1.5) - Ortscode_Geschoßbezeichnung: E02; OKFF: 7.5
SMT | H2 Ebene +2 | 2.41 | 1.9715 | TI-2F-AG-D-O | 3.20964 | 150 | 200 | 100 | 100 |  |  | EI2 30 | 0 | no | yes | no |  |  | 0 | E02 | 3.1 | Türmakro, -SmartPart | SMT | TI-2F-AG-D-O | MainObject | SmartPartCompressed | 100 | 7.21 | - | - | BZ | OTS | 0 | ja | - | FWS | EMF | - | 7.5 |  | E02-F03-001-69 | L | 0 | SB | - | - | - |  | - | S | S | E | PZ(v) | KD | 1 |  | - |  | Door | 1215Rau0000006920 | 1213Mak0813004862 | St | 69 | no |  | Stahl-Glas-Tür | (B), E, H | Typ | 0 | 3.1 | TGR-Makro | PlanNo. | TGR 1.5 | MainObject | SmartPartCompressed | 9.1265 | 1.5 | 2 | 1215Rau0000006905 | 1213Mak0813220030 | St | AllplanAttributes (TGR 1.5) - Ortscode_Geschoßbezeichnung: E02; OKFF: 7.5; AllplanAttributes (SMT) - Text2: -; ash T_Steuerung (BG): E, H
SMT | H2 Ebene +2 | 2.41 | 1.6825 | TI-2F-AG-D-O | 2.7722 | 150 | 200 | 100 | 100 | NEW | no | EI2 30 | 0 | no | yes | no | SA | Metallbau-, Schlosserarbeiten | 0 | E02 | 3.1 | Türmakro | SMT | TI-2F-AG-D-O | MainObject | SmartPartCompressed | 100 | 7.21 | - | N | BZ | OTS | 0 | ja | - | FWS | EMF | - | 7.5 | 0.000000 | E02-F05-002-40 | L | 0 | SB | A | - | - | - | - | S | S | E | PZ(v) | KD | 1 | - | - | BS | Door | 1215Rau0000006929 | 1213Mak0813462287 | St | 40 | no | - | Stahl-Glas-Tür | (B), E, H | Typ | 0 | 3.1 | TGR-Makro | PlanNo. | TGR 1.5 | MainObject | SmartPartCompressed | 8.8375 | 1.5 | 2 | 1215Rau0000006905 | 1213Mak0813221211 | St | AllplanAttributes (SMT) - ash T_Material Oberlicht: -; ash D_Detailverweis: D9; Text2: -; ash T_Steuerung (BG): E, H; ash D_Plannummer: 1684; AllplanAttributes (TGR 1.5) - Ortscode_Geschoßbezeichnung: E02; OKFF: 7.5
FS-Vorhang | H2 Ebene +2 | 2.57 | 1.84 | TI-1F-UZ-M-ZK | 0 | 150 | 200 | 120 | 0 | NEW | no | EW 60 | 0 | no | yes | no | - | AllplanAttributes (FS-Vorhang) - Gewerk: Zimmer- und Holzbauarbeiten; V6: 0 m; V7: 0 m; V8: 0 m; V9: 0; Ortscode_Geschoßbezeichnung: E02; Programmversion: 3.1; Objektname: Brandschutzvorhang; Text1: S200 C2; Bezeichnung: FS-Vorhang; Material: TI-1F-UZ-M-ZK; Plugin_Bezeichnung: MainObject; Plugin_Objektname: SmartPartCompressed; Glasanteil_berücksichtigen: 100; Version: 7.21; ash T_Sichtschutz: -; ash R_Verweis Wandansicht: -; ash T_Zulage Schachttür: no; ash T_Dichtschließend: no; ash T_Panik: -; ash T_Zarge_Typ: U; ash T_Türschließer: -; ash T_Gewerk Los: -; ash T_Erforderl. Durchgangsbreite: 0 m; ash T_Türblatt sichtbar 2D: ja; ash T_Zusatzfunktion Panikschloss: -; ash T_Fluchtwegsicherung: -; ash T_Standflügel-Betätigung: -; ash T_Zusatzfunktion Türschließer: -; ash T_Türschließer-Montage: -; ash T_Feststellanlage (FSA): -; ash T_Zusätzliche Rauchmelder: -; ash T_Zusätzl. Anschluss an BMA: -; ash T_Impulsgeber: -; ash T_Sicherheits-Sensorleisten: -; ash T_Anschl. an Zuttrittskontrolle: -; ash T_Anschl. an Einbruchmeld.anl.: -; ash T_Klemmschutz: -; ash T_LV-Positions-Nr.: -; ash T_Plan-Nr.: -; ash T_Sonstiges, Bemerkungen: -; OKFF: 7.5; ash T_Bodentürstopper: -; ash T_nicht abschließbar: no; ash T_Material Seitenteil: -; ash T_Strahlenschutz: 0.000000; ash T_Tür-Nr.: FS-Vorhang; ash T_Kantengeometrie: -; ash T_Kantenmaterial: -; ash T_Blatt_Oberfläche: L; ash T_Erford. Durgangshöhe: 0 m; ash T_Laserschutz: -; ash T_Rammschutz: -; ash T_Fluchtwegrichtung: -; ash T_Anschlag Gangflügel: -; ash T_Bodendichtung: -; ash T_Lüftungsgitter: 0 m2; ash T_Feuchtebeständigkeit: -; ash T_E_Öffner: -; ash T_Automatik_Antrieb: -; ash T_Sturz: -; ash T_Blatt_Material: AL; ash T_Schlossfunktion: -; ash T_Schliesszylinder: -; ash T_Beschlag: -; ash T_Material Oberlicht: -; ash T_Glasausschnitt: -; ash T_Sonder_Wandmaterial: -; ash T_Anz_Reedkontakte: 0; ash T_Anz_Riegelkontakte: 0; ash T_Schallschutz: -; ash T_Zarge_Material: S; ash T_Bodeneinstand: -; ash T_Raum zugehörigkeit: BS; ash T_Blatt_Farbe: -; Attributset-Objekt: Door; P_ID: 1115Rau0000005163; Allright_Bauteil_ID: 1213Mak0813503813; Abrechnungsart: St
FS-Vorhang | H2 Ebene +2 | 2.57 | 1.84 | TI-1F-UZ-M-ZK | 0 | 150 | 200 | 120 | 0 | NEW | no | EW 60 | 0 | no | yes | no | - | AllplanAttributes (FS-Vorhang) - Gewerk: Zimmer- und Holzbauarbeiten; V6: 0 m; V7: 0 m; V8: 0 m; V9: 0; Ortscode_Geschoßbezeichnung: E02; Programmversion: 3.1; Objektname: Brandschutzvorhang; Text1: S200 C2; Bezeichnung: FS-Vorhang; Material: TI-1F-UZ-M-ZK; Plugin_Bezeichnung: MainObject; Plugin_Objektname: SmartPartCompressed; Glasanteil_berücksichtigen: 100; Version: 7.21; ash T_Sichtschutz: -; ash R_Verweis Wandansicht: -; ash T_Zulage Schachttür: no; ash T_Dichtschließend: no; ash T_Panik: -; ash T_Zarge_Typ: U; ash T_Türschließer: -; ash T_Gewerk Los: -; ash T_Erforderl. Durchgangsbreite: 0 m; ash T_Türblatt sichtbar 2D: ja; ash T_Zusatzfunktion Panikschloss: -; ash T_Fluchtwegsicherung: -; ash T_Standflügel-Betätigung: -; ash T_Zusatzfunktion Türschließer: -; ash T_Türschließer-Montage: -; ash T_Feststellanlage (FSA): -; ash T_Zusätzliche Rauchmelder: -; ash T_Zusätzl. Anschluss an BMA: -; ash T_Impulsgeber: -; ash T_Sicherheits-Sensorleisten: -; ash T_Anschl. an Zuttrittskontrolle: -; ash T_Anschl. an Einbruchmeld.anl.: -; ash T_Klemmschutz: -; ash T_LV-Positions-Nr.: -; ash T_Plan-Nr.: -; ash T_Sonstiges, Bemerkungen: -; OKFF: 7.5; ash T_Bodentürstopper: -; ash T_nicht abschließbar: no; ash T_Material Seitenteil: -; ash T_Strahlenschutz: 0.000000; ash T_Tür-Nr.: FS-Vorhang; ash T_Kantengeometrie: -; ash T_Kantenmaterial: -; ash T_Blatt_Oberfläche: L; ash T_Erford. Durgangshöhe: 0 m; ash T_Laserschutz: -; ash T_Rammschutz: -; ash T_Fluchtwegrichtung: -; ash T_Anschlag Gangflügel: -; ash T_Bodendichtung: -; ash T_Lüftungsgitter: 0 m2; ash T_Feuchtebeständigkeit: -; ash T_E_Öffner: -; ash T_Automatik_Antrieb: -; ash T_Sturz: -; ash T_Blatt_Material: AL; ash T_Schlossfunktion: -; ash T_Schliesszylinder: -; ash T_Beschlag: -; ash T_Material Oberlicht: -; ash T_Glasausschnitt: -; ash T_Sonder_Wandmaterial: -; ash T_Anz_Reedkontakte: 0; ash T_Anz_Riegelkontakte: 0; ash T_Schallschutz: -; ash T_Zarge_Material: S; ash T_Bodeneinstand: -; ash T_Raum zugehörigkeit: BS; ash T_Blatt_Farbe: -; Attributset-Objekt: Door; P_ID: 1115Rau0000005163; Allright_Bauteil_ID: 1213Mak0813503602; Abrechnungsart: St
SMT | H2 Ebene +1 | 2.7 | 1.983 | TA-1F-AG-D-2S-O | 3.41025 | 200 | 200 | 50 | 50 | NEW | yes | 0 | 1 |  |  |  | RC 2 | Metallbau-, Schlosserarbeiten | 0 | E00 | 3.1 | Türmakro | SMT | TA-1F-AG-D-2S-O | MainObject | SmartPartCompressed | 100 | 7.21 | - | - | - | - | 1.05 | ja | - | - | - | - | 3.75 | 0.000000 | TA-1FL-D-1S-E01-012 | - | 2.05 | - | - | - | - | - | - | - | - | - | - | - | 0 | - | - | BS | Door | 1115Rau0000005181 | 1155Mak0813754086 | St | 6 |  |  |  |  |  |  |  |  |  |  |  |  |  |  |  |  |  |  | U23 | AllplanAttributes (SMT) - ash T_Unterschnitt: -; ash T_Material Oberlicht: -; g-Wert: 0,51; Pset_DoorCommon - AcousticRating: 32; Reference: T_Typ11
SMT | H2 Ebene +1 | 2.7 | 2.013 | TA-1F-AG-D-2S-O | 3.5563 | 150 | 0 | 50 | 50 | NEW | yes | 0 | 1 |  |  |  | RC 1 | Metallbau-, Schlosserarbeiten | 0 | E01 | 3.1 | Türmakro | SMT | TA-1F-AG-D-2S-O | MainObject | SmartPartCompressed | 100 | 7.21 | - | - | - | - | 1.05 | ja | - | - | - | - | 3.75 | 0.000000 | TA-1FR-D-1S-E01-013 | - | 2.05 | - | - | - | - | - | - | - | - | - | - | - | 0 | - | - | BS | Door | 1165Rau0000004819 | 1155Mak0000002425 | St | AllplanAttributes (SMT) - ash T_Unterschnitt: -; ash T_Material Oberlicht: -; Sonnenschutztyp: Movable; g-Wert: 0,51; Pset_DoorCommon - AcousticRating: 32; Reference: T_Typ12
SMT | H2 Ebene +1 | 2.41 | 3.668 | TI-1F-AG-S | 6.75221 | 150 | 0 | 50 | 50 | NEW | no |  | 0 | no | no | no | SA | Metallbau-, Schlosserarbeiten | 0 | E01 | 3.1 | Türmakro | SMT | TI-1F-AG-S | MainObject | SmartPartCompressed | 100 | 7.21 | - | - | - | - | 0 | ja | - | - | - |  | 3.75 | 0.000000 | E01-050-002-92 | L | 0 | - | - | - | - | - | - | - | SG | - | PZ | DD | 0 | - | - | BGS | Door | 1166Rau0000034085 | 1163Mak0814483568 | St | 92 | no | - |  |  |  |  |  |  |  |  |  |  |  |  |  |  |  |  | U100 | AllplanAttributes (SMT) - ash T_Unterschnitt: 1; AllplanAttributes (TGR 1.6) - Codetext: Typ; V6: 0 m; V7: 0 m; V8: 0 m; V9: 0; Programmversion: 3.1; Objektname: TGR-Makro; Text1: PlanNo.; Bezeichnung: TGR 1.6; Plugin_Bezeichnung: MainObject; Plugin_Objektname: SmartPartCompressed; Gesamtlänge: 10.768; Version: 1.6; ash T_Türprofilnummer: 2; Allright_Bauteil_ID: 1163Mak0814181011; Abrechnungsart: St; Positionsnummer_Text: U100
SMT | H2 Ebene +1 | 2.41 | 3.61 | TI-1F-AG-S | 6.63447 | 150 | 0 | 50 | 50 | NEW | no |  | 0 | no | no | no |  | Metallbau-, Schlosserarbeiten | 0 | E01 | 3.1 | Türmakro | SMT | TI-1F-AG-S | MainObject | SmartPartCompressed | 100 | 7.21 | - | - | - | - | 0 | ja | - | - | - |  | 3.75 | 0.000000 | E01-048-002-85 | L | 0 | - | - | - | - | - | - | - | SG | - | PZ | DD | 0 | - | - | BS | Door | 1166Rau0000033183 | 1163Mak0814483356 | St | 85 | no |  |  |  |  |  |  |  |  |  |  |  |  |  |  |  |  |  | U100 | AllplanAttributes (SMT) - ash T_Unterschnitt: 1; AllplanAttributes (TGR 1.6) - Codetext: Typ; V6: 0 m; V7: 0 m; V8: 0 m; V9: 0; Programmversion: 3.1; Objektname: TGR-Makro; Text1: PlanNo.; Bezeichnung: TGR 1.6; Plugin_Bezeichnung: MainObject; Plugin_Objektname: SmartPartCompressed; Gesamtlänge: 10.71; Version: 1.6; ash T_Türprofilnummer: 2; Allright_Bauteil_ID: 1163Mak0814180738; Abrechnungsart: St; Positionsnummer_Text: U100
SMT | H2 Ebene +1 | 2.53 | 2.3 | TI-1F-AG-D-1S-ZK | 4.00308 | 150 | 100 | 0 | 0 | NEW | no | EI2 30 | 0 | no | yes | no |  | Zimmer- und Holzbauarbeiten | 0 | E01 | 3.1 | Türmakro | SMT | TI-1F-AG-D-1S-ZK | MainObject | SmartPartCompressed | 100 | 7.21 | - | N | BZ | OTS | 0 | ja | - | FWS | - | ZK | 3.75 | 0.000000 | E01-T03-001-88 | L | 0 | SB | A | - | - | TÖ + FTÖ | - |  | S | E | PZ(v) | KD | 1 | - | - | BS | Door | 1165Rau0000004771 | 1163Mak0812437060 | St | 88 | no | - | Stahl-Glas-Tür | E, H |  |  |  |  |  |  |  |  |  |  |  |  |  |  | U100 | AllplanAttributes (SMT) - Text2: X; ash T_Steuerung (BG): E, H
SMT | H2 Ebene +1 | 2.65 | 2.55 | TI-1F-AG-D-1S-O | 4.58865 | 150 | 0 | 50 | 50 |  |  | EI2 60 | 0 | no | yes | no |  | Zimmer- und Holzbauarbeiten | 0 | E01 | 3.0 | Türmakro, -SmartPart | SMT | TI-1F-AG-D-1S-O | MainObject | SmartPartCompressed | 100 | 8.11 | - | - | BZ | OTS | 0 | ja | - | - | - | - | 3.75 |  | E01-008-001-80 | L | 0 | SB | - | - | - | - | - | S | S | - | PZ | DD | 0 |  | - | BS | Door | 1166Rau0000033183 | 1163Mak0814410933 | St | 80 | no |  | Stahl-Glas-Tür |  | Typ | 0 | 3.1 | TGR-Makro | PlanNo. | TGR 1.5 | MainObject | SmartPartCompressed | 9.705 | 1.5 | 8 | 1165Rau0000004701 | 1163Mak0814472682 | St | U100 | AllplanAttributes (TGR 1.5) - Positionsnummer_Text: U100
SMT | H2 Ebene +1 | 2.41 | 2.063 | TI-1F-SG-D-M | 3.40087 | 150 | 200 | 100 | 100 | NEW | no | EI2 30 | 0 | no | yes | no | SA | Zimmer- und Holzbauarbeiten | 0 | E01 | 3.0 | Türmakro | SMT | TI-1F-SG-D-M | MainObject | SmartPartCompressed | 100 | 8.11 | - | N | BZ | OTS | 0 | ja | - | FWS | EMF | ZK | 3.75 | 0.000000 | E01-F03-001-94 | L | 0 | SB | A | - | - | TÖ + FTÖ | - | S | S | E | PZ(v) | KD | 1 | - | - | BGS | Door | 1165Rau0000004701 | 1163Mak0814411254 | St | 94 | no | - | Stahl-Glas-Tür | B, E, H | Typ | 0 | 3.1 | TGR-Makro | PlanNo. | TGR 1.5 | MainObject | SmartPartCompressed | 9.218 | 1.5 | 6 | 1165Rau0000004701 | 1163Mak0814008772 | St | U100 | AllplanAttributes (SMT) - ash D_Detailverweis: D1; Text2: X; ash T_Steuerung (BG): E, H; ash D_Plannummer: 1684; AllplanAttributes (TGR 1.5) - Positionsnummer_Text: U100
SMT | H2 Ebene +1 | 2.41 | 1.9715 | TI-2F-AG-D-O | 3.20964 | 150 | 200 | 100 | 100 |  |  | EI2 30 | 0 | no | yes | no | SA |  | 0 | E01 | 3.1 | Türmakro, -SmartPart | SMT | TI-2F-AG-D-O | MainObject | SmartPartCompressed | 100 | 7.21 | - | - | BZ | OTS | 0 | ja | - | FWS | EMF | - | 3.75 | 0.000000 | E01-F04-001-69 | L | 0 | SB | - | - | - |  | - | S | S | E | PZ(v) | KD | 1 | - | - |  | Door | 1165Rau0000004808 | 1163Mak0814387536 | St | 69 | no | - | Stahl-Glas-Tür | (B), E, H | Typ | 0 | 3.1 | TGR-Makro | PlanNo. | TGR 1.5 | MainObject | SmartPartCompressed | 9.1265 | 1.5 | 2 | 1165Rau0000067051 | 1163Mak0814147387 | St | U100 | AllplanAttributes (SMT) - Text2: -; ash T_Steuerung (BG): E, H; AllplanAttributes (TGR 1.5) - Positionsnummer_Text: U100
SMT | H2 Ebene +1 | 2.41 | 1.355 | TI-1F-AG-D | 2.0493 | 150 | 100 | 0 | 0 | NEW | no | EI2 30 | 0 | no | yes | no | SA | Zimmer- und Holzbauarbeiten | 0 | E01 | 3.1 | Türmakro | SMT | TI-1F-AG-D | MainObject | SmartPartCompressed | 100 | 7.21 | - | - | UZ | OTS | 0 | ja | - | - | EMF | - | 3.75 | 0.000000 | E01-013a-001-165 | L | 0 | - | - | - | Ja |  | - | - | S | E | PZ | DD | 1 | - | ST | BS | Door | 1166Rau0000033283 | 1163Mak0814120383 | St | 165 | no | - | Stahl-Glas-Tür | E | Typ | 0 | 3.1 | TGR-Makro | PlanNo. | TGR 1.5 | MainObject | SmartPartCompressed | 8.51 | 1.5 | 2 | 1166Rau0000034222 | 1163Mak0814147015 | St | U100 | AllplanAttributes (SMT) - ash D_Detailverweis: D3; ash D_Plannummer: 1684; AllplanAttributes (TGR 1.5) - Positionsnummer_Text: U100
SMT | H2 Ebene +1 | 2.41 | 1.325 | TI-1F-AG-D | 1.9899 | 150 | 100 | 0 | 0 | NEW | no | EI2 60 | 0 | no | yes | no |  | Zimmer- und Holzbauarbeiten | 0 | E01 | 3.1 | Türmakro, -SmartPart | SMT | TI-1F-AG-D | MainObject | SmartPartCompressed | 100 | 7.21 | - | - | UZ | OTS | 0 | ja | - | - | EMF | - | 3.75 | 0.000000 | E01-063-001-158 | L | 0 | - | - | - | Ja |  | - | - | S | E | PZ | DD | 1 | - | ST | BS | Door | 1166Rau0000034222 | 1163Mak0813982059 | St | 158 | no |  | Stahl-Glas-Tür | E | Typ | 0 | 3.1 | TGR-Makro | PlanNo. | TGR 1.5 | MainObject | SmartPartCompressed | 8.48 | 1.5 | 2 | 1166Rau0000034222 | 1163Mak0814128576 | St | U100 | AllplanAttributes (TGR 1.5) - Positionsnummer_Text: U100
SMT | H2 Ebene +1 | 2.41 | 1.968 | TI-1F-SG-D-M | 3.20232 | 150 | 200 | 100 | 100 | NEW | no | EI2 30 | 0 | no | yes | no | SA | Zimmer- und Holzbauarbeiten | 0 | E01 | 3.0 | Türmakro | SMT | TI-1F-SG-D-M | MainObject | SmartPartCompressed | 100 | 8.11 | - | N | BZ | OTS | 0 | ja |  | FWS | EMF | ZK | 3.75 | 0.000000 | E01-F07-001-94a | L | 0 | SB | A | - | - | TÖ + FTÖ | - | S | S | E | PZ(v) | KD | 1 | - | - | BGS | Door | 1165Rau0000004701 | 1163Mak0814470837 | St | 94a | no | - | Stahl-Glas-Tür | B, E, H | Typ | 0 | 3.1 | TGR-Makro | PlanNo. | TGR 1.5 | MainObject | SmartPartCompressed | 9.123 | 1.5 | 2 | 1165Rau0000004701 | 1163Mak0814141964 | St | U100 | AllplanAttributes (SMT) - Text2: X; ash T_Steuerung (BG): E, H; AllplanAttributes (TGR 1.5) - Positionsnummer_Text: U100
SMT | H2 Ebene +1 | 2.41 | 1.9715 | TI-2F-AG-D-O | 3.20964 | 150 | 200 | 100 | 100 |  |  | EI2 30 | 0 | no | yes | no | SA |  | 0 | E01 | 3.1 | Türmakro, -SmartPart | SMT | TI-2F-AG-D-O | MainObject | SmartPartCompressed | 100 | 7.21 | - | - | UZ | OTS | 0 | ja | - | FWS | EMF | - | 3.75 | 0.000000 | E01-F09a-001-105 | L | 0 | SB | A | - | - |  | - | - | S | E | PZ(v) | KD | 1 | - | ST |  | Door | 1165Rau0000004819 | 1163Mak0814388690 | St | 105 | no | - | Stahl-Glas-Tür | (B), E, H | Typ | 0 | 3.1 | TGR-Makro | PlanNo. | TGR 1.5 | MainObject | SmartPartCompressed | 9.1265 | 1.5 | 2 | 1165Rau0000004701 | 1163Mak0814142796 | St | U100 | AllplanAttributes (SMT) - Text2: -; ash T_Steuerung (BG): E, H; AllplanAttributes (TGR 1.5) - Positionsnummer_Text: U100
SMT | H2 Ebene +1 | 2.65 | 2.55 | TI-1F-AG-D-1S-O | 4.70025 | 150 | 0 | 50 | 50 | NEW | no | EI2 30 | 0 | no | yes | no |  | Zimmer- und Holzbauarbeiten | 0 | E01 | 3.0 | Türmakro | SMT | TI-1F-AG-D-1S-O | MainObject | SmartPartCompressed | 100 | 8.11 | - | - | BZ | OTS | 0 | ja | - | - | - |  | 3.75 | 0.000000 | E01-055-001-95 | L | 0 | SB | - | - | - | - | - | S | S | - | PZ | DD | 0 | - | - | BS | Door | 1166Rau0000034085 | 1163Mak0814470193 | St | 95 | no |  | Stahl-Glas-Tür |  | Typ | 0 | 3.1 | TGR-Makro | PlanNo. | TGR 1.5 | MainObject | SmartPartCompressed | 9.705 | 1.5 | 6 | 1165Rau0000004701 | 1163Mak0814479234 | St | U100 | AllplanAttributes (TGR 1.5) - Positionsnummer_Text: U100
SMT | H2 Ebene +1 | 2.41 | 1.6825 | TI-2F-AG-D-O | 2.70357 | 200 | 200 | 100 | 100 | NEW | no | EI2 30 | 0 | no | yes | no | SA | Metallbau-, Schlosserarbeiten | 0 | E00 | 3.1 | Türmakro | SMT | TI-2F-AG-D-O | MainObject | SmartPartCompressed | 100 | 7.21 | - | N | BZ | OTS | 0 | ja | - | FWS | EMF | - | 3.75 | 0.000000 | E01-F06-001-40 | L | 0 | SB | A | - | - |  | - | S | S | E | PZ(v) | KD | 1 | - | - | BS | Door | 1165Rau0000004677 | 1163Mak0814386625 | St | 40 | no | - | Stahl-Glas-Tür | (B), E, H | Typ | 0 | 3.1 | TGR-Makro | PlanNo. | TGR 1.5 | MainObject | SmartPartCompressed | 8.8375 | 1.5 | 2 | 1165Rau0000067051 | 1163Mak0814148761 | St | U100 | AllplanAttributes (SMT) - ash D_Detailverweis: D9; Text2: -; ash T_Steuerung (BG): E, H; ash D_Plannummer: 1684; AllplanAttributes (TGR 1.5) - Positionsnummer_Text: U100
FS-Vorhang | H2 Ebene +1 | 2.57 | 1.84 | TI-1F-UZ-M-ZK | 0 | 200 | 200 | 120 | 0 | NEW | no | EW 60 | 0 | no | yes | no | - | AllplanAttributes (FS-Vorhang) - Gewerk: Zimmer- und Holzbauarbeiten; V6: 0 m; V7: 0 m; V8: 0 m; V9: 0; Ortscode_Geschoßbezeichnung: E00; Programmversion: 3.1; Objektname: Brandschutzvorhang; Text1: S200 C2; Bezeichnung: FS-Vorhang; Material: TI-1F-UZ-M-ZK; Plugin_Bezeichnung: MainObject; Plugin_Objektname: SmartPartCompressed; Glasanteil_berücksichtigen: 100; Version: 7.21; ash T_Sichtschutz: -; ash R_Verweis Wandansicht: -; ash T_Zulage Schachttür: no; ash T_Dichtschließend: no; ash T_Panik: -; ash T_Zarge_Typ: U; ash T_Türschließer: -; ash T_Gewerk Los: -; ash T_Erforderl. Durchgangsbreite: 0 m; ash T_Türblatt sichtbar 2D: ja; ash T_Zusatzfunktion Panikschloss: -; ash T_Fluchtwegsicherung: -; ash T_Standflügel-Betätigung: -; ash T_Zusatzfunktion Türschließer: -; ash T_Türschließer-Montage: -; ash T_Feststellanlage (FSA): -; ash T_Zusätzliche Rauchmelder: -; ash T_Zusätzl. Anschluss an BMA: -; ash T_Impulsgeber: -; ash T_Sicherheits-Sensorleisten: -; ash T_Anschl. an Zuttrittskontrolle: -; ash T_Anschl. an Einbruchmeld.anl.: -; ash T_Klemmschutz: -; ash T_LV-Positions-Nr.: -; ash T_Plan-Nr.: -; ash T_Sonstiges, Bemerkungen: -; OKFF: 0; ash T_Bodentürstopper: -; ash T_nicht abschließbar: no; ash T_Material Seitenteil: -; ash T_Strahlenschutz: 0.000000; ash T_Tür-Nr.: FS-Vorhang; ash T_Kantengeometrie: -; ash T_Kantenmaterial: -; ash T_Blatt_Oberfläche: L; ash T_Erford. Durgangshöhe: 0 m; ash T_Laserschutz: -; ash T_Rammschutz: -; ash T_Fluchtwegrichtung: -; ash T_Anschlag Gangflügel: -; ash T_Bodendichtung: -; ash T_Lüftungsgitter: 0 m2; ash T_Feuchtebeständigkeit: -; ash T_E_Öffner: -; ash T_Automatik_Antrieb: -; ash T_Sturz: -; ash T_Blatt_Material: AL; ash T_Schlossfunktion: -; ash T_Schliesszylinder: -; ash T_Beschlag: -; ash T_Material Oberlicht: -; ash T_Glasausschnitt: -; ash T_Sonder_Wandmaterial: -; ash T_Anz_Reedkontakte: 0; ash T_Anz_Riegelkontakte: 0; ash T_Schallschutz: -; ash T_Zarge_Material: S; ash T_Bodeneinstand: -; ash T_Raum zugehörigkeit: BS; ash T_Blatt_Farbe: -; Attributset-Objekt: Door; P_ID: 1115Rau0000005163; Allright_Bauteil_ID: 1163Mak0814454134; Abrechnungsart: St
FS-Vorhang | H2 Ebene +1 | 2.57 | 1.84 | TI-1F-UZ-M-ZK | 0 | 200 | 200 | 120 | 0 | NEW | no | EW 60 | 0 | no | yes | no | - | AllplanAttributes (FS-Vorhang) - Gewerk: Zimmer- und Holzbauarbeiten; V6: 0 m; V7: 0 m; V8: 0 m; V9: 0; Ortscode_Geschoßbezeichnung: E00; Programmversion: 3.1; Objektname: Brandschutzvorhang; Text1: S200 C2; Bezeichnung: FS-Vorhang; Material: TI-1F-UZ-M-ZK; Plugin_Bezeichnung: MainObject; Plugin_Objektname: SmartPartCompressed; Glasanteil_berücksichtigen: 100; Version: 7.21; ash T_Sichtschutz: -; ash R_Verweis Wandansicht: -; ash T_Zulage Schachttür: no; ash T_Dichtschließend: no; ash T_Panik: -; ash T_Zarge_Typ: U; ash T_Türschließer: -; ash T_Gewerk Los: -; ash T_Erforderl. Durchgangsbreite: 0 m; ash T_Türblatt sichtbar 2D: ja; ash T_Zusatzfunktion Panikschloss: -; ash T_Fluchtwegsicherung: -; ash T_Standflügel-Betätigung: -; ash T_Zusatzfunktion Türschließer: -; ash T_Türschließer-Montage: -; ash T_Feststellanlage (FSA): -; ash T_Zusätzliche Rauchmelder: -; ash T_Zusätzl. Anschluss an BMA: -; ash T_Impulsgeber: -; ash T_Sicherheits-Sensorleisten: -; ash T_Anschl. an Zuttrittskontrolle: -; ash T_Anschl. an Einbruchmeld.anl.: -; ash T_Klemmschutz: -; ash T_LV-Positions-Nr.: -; ash T_Plan-Nr.: -; ash T_Sonstiges, Bemerkungen: -; OKFF: 0; ash T_Bodentürstopper: -; ash T_nicht abschließbar: no; ash T_Material Seitenteil: -; ash T_Strahlenschutz: 0.000000; ash T_Tür-Nr.: FS-Vorhang; ash T_Kantengeometrie: -; ash T_Kantenmaterial: -; ash T_Blatt_Oberfläche: L; ash T_Erford. Durgangshöhe: 0 m; ash T_Laserschutz: -; ash T_Rammschutz: -; ash T_Fluchtwegrichtung: -; ash T_Anschlag Gangflügel: -; ash T_Bodendichtung: -; ash T_Lüftungsgitter: 0 m2; ash T_Feuchtebeständigkeit: -; ash T_E_Öffner: -; ash T_Automatik_Antrieb: -; ash T_Sturz: -; ash T_Blatt_Material: AL; ash T_Schlossfunktion: -; ash T_Schliesszylinder: -; ash T_Beschlag: -; ash T_Material Oberlicht: -; ash T_Glasausschnitt: -; ash T_Sonder_Wandmaterial: -; ash T_Anz_Reedkontakte: 0; ash T_Anz_Riegelkontakte: 0; ash T_Schallschutz: -; ash T_Zarge_Material: S; ash T_Bodeneinstand: -; ash T_Raum zugehörigkeit: BS; ash T_Blatt_Farbe: -; Attributset-Objekt: Door; P_ID: 1115Rau0000005163; Allright_Bauteil_ID: 1163Mak0814454067; Abrechnungsart: St
SMT | H2 Ebene +1 | 2.41 | 1.965 | TI-2F-AG-D-O | 3.19605 | 150 | 200 | 100 | 100 | NEW | no | EI2 30 | 0 | no | yes | no | SA | Betonarbeiten | 0 | E01 | 3.1 | Türmakro, -SmartPart | SMT | TI-2F-AG-D-O | MainObject | SmartPartCompressed | 100 | 7.21 | - | N | UZ | OTS | 0 | ja | - | FWS | EMF | - | 3.75 | 0.000000 | E01-F09b-001-153 | L | 0 | SB | A | - | - |  | - | - | S | E | PZ(v) | KD | 1 | - | ST |  | Door | 1165Rau0000004819 | 1163Mak0814389604 | St | 153 | no | - | Stahl-Glas-Tür | (B), E, H | Typ | 0 | 3.1 | TGR-Makro | PlanNo. | TGR 1.5 | MainObject | SmartPartCompressed | 9.12 | 1.5 | 2 | 1165Rau0000067051 | 1163Mak0814146276 | St | U100 | Pset_DoorCommon - AcousticRating: 0; Reference: Codetext; AllplanAttributes (SMT) - Text2: -; ash T_Steuerung (BG): E, H; Codetext: Codetext; Funktion: Flurtür; Tragendes Bauteil: yes; Typ: 0; Brennbares Material: no; Brandverhalten: 0; Brandabschnittsdefinierendes Bauteil: no; Brandschutzklasse: A; AllplanAttributes (TGR 1.5) - Positionsnummer_Text: U100
SMT | H2 Ebene +1 | 2.41 | 1.9713 | TI-2F-AG-D-O | 3.20922 | 150 | 200 | 100 | 100 | NEW | no | EI2 30 | 0 | no | yes | no | SA | Betonarbeiten | 0 | E01 | 3.1 | Türmakro, -SmartPart | SMT | TI-2F-AG-D-O | MainObject | SmartPartCompressed | 100 | 7.21 | - | N | BZ | OTS | 0 | ja | - | FWS | EMF | - | 3.75 | 0.000000 | E01-F03b-002-22 | L | 0 | SB | A | - | - |  | - | S | S | E | PZ(v) | KD | 1 | - | - |  | Door | 1165Rau0000004808 | 1163Mak0814390371 | St | 22 | no | - | Stahl-Glas-Tür | (B), E, H | Typ | 0 | 3.1 | TGR-Makro | PlanNo. | TGR 1.5 | MainObject | SmartPartCompressed | 9.1263 | 1.5 | 2 | 1166Rau0000034222 | 1163Mak0814149191 | St | U100 | Pset_DoorCommon - AcousticRating: 0; Reference: Codetext; AllplanAttributes (SMT) - Text2: -; ash T_Steuerung (BG): E, H; Codetext: Codetext; Funktion: Flurtür; Tragendes Bauteil: yes; Typ: 0; Brennbares Material: no; Brandverhalten: 0; Brandabschnittsdefinierendes Bauteil: no; Brandschutzklasse: A; AllplanAttributes (TGR 1.5) - Positionsnummer_Text: U100
SMT | H2 Ebene +1 | 2.41 | 1.9425 | TI-1F-SG-D-M | 3.14902 | 150 | 200 | 100 | 100 | NEW | no | EI2 30 | 0 | no | yes | no | SA | Zimmer- und Holzbauarbeiten | 0 | E01 | 3.1 | Türmakro, -SmartPart | SMT | TI-1F-SG-D-M | MainObject | SmartPartCompressed | 100 | 7.21 | - | N | BZ | - | 0 | ja |  | FWS | - | ZK | 3.75 | 0.000000 | E01-F09a-001-162 | L | 0 | SB | A | - | - | TÖ + FTÖ | M1 |  | S | E | PZ(v) | KD | 1 | - | - |  | Door | 1165Rau0000067051 | 1163Mak0812440018 | St | 162 | no | - | Stahl-Glas-Tür | E, G, H | Typ | 0 | 3.1 | TGR-Makro | PlanNo. | TGR 1.5 | MainObject | SmartPartCompressed | 9.0975 | 1.5 | 6 | 1165Rau0000067051 | 1163Mak0814008708 | St | U100 | Pset_DoorCommon - AcousticRating: 0; Reference: Codetext; AllplanAttributes (SMT) - Text2: X; ash T_Steuerung (BG): B, C, E, H; Codetext: Codetext; Funktion: Flurtür; Tragendes Bauteil: yes; Typ: 0; Brennbares Material: no; Brandverhalten: 0; Brandabschnittsdefinierendes Bauteil: no; Brandschutzklasse: A; AllplanAttributes (TGR 1.5) - Positionsnummer_Text: U100
SMT | H2 Ebene 0 | 2.7 | 5.89 | TA-2F-AG-D-2S | 11.4029 | 200 | 200 | 80 | 70 | NEW | yes | 0 | 1.4 |  |  |  | RC 2 | Metallbau-, Schlosserarbeiten | 0 | E00 | 3.0 | Türmakro | SMT | TA-2F-AG-D-2S | MainObject | SmartPartCompressed | 100 | 9.62 | - | - | - | - | 1.2 | ja | - | - | - | - | 0 | 0.000000 | TA-2FLR-D-2S-E00-009 | - | 2.05 | - | - | - | - | - | M2 | - | - | M | PZ | SP | 0 | - | - | BS | Door | 1115Rau0000005147 | 1105Mak0811632322 | St | 1 |  |  |  | E, F, G |  |  |  |  |  |  |  |  |  |  |  |  |  |  | U23 | AllplanAttributes (SMT) - ash T_Unterschnitt: -; ash T_Material Oberlicht: -; ash D_Detailverweis: Typ8; g-Wert: 0,35; ash T_Steuerung (BG): B, C, F; ash D_Plannummer: D1752; Pset_DoorCommon - AcousticRating: 32; Reference: T_Typ8
SMT | H2 Ebene 0 | 2.7 | 2.013 | TA-1F-AG-D-2S-O | 3.47775 | 200 | 0 | 50 | 50 | NEW | yes | 0 | 1 |  |  |  | RC 2 | Metallbau-, Schlosserarbeiten | 0 | E00 | 3.1 | Türmakro | SMT | TA-1F-AG-D-2S-O | MainObject | SmartPartCompressed | 100 | 7.21 | - | - | - | - | 1.05 | ja | - | - | - | - | 0 | 0.000000 | TA-1FR-D-2S-E00-006 | - | 2.05 | - | - | - | - | - | - | - | - | - | PZ | - | 0 | - | - | BS | Door | 1115Rau0000005220 | 1105Mak0811622567 | St | 9 |  |  |  |  |  |  |  |  |  |  |  |  |  |  |  |  |  |  | U23 | AllplanAttributes (SMT) - ash T_Unterschnitt: -; ash T_Material Oberlicht: -; ash D_Detailverweis: Typ6; g-Wert: 0,51; ash D_Plannummer: D1755; Pset_DoorCommon - AcousticRating: 32; Reference: T_Typ6
SMT | H2 Ebene 0 | 2.7 | 1.983 | TA-1F-AG-D-2S-O | 3.41025 | 200 | 200 | 50 | 50 | NEW | yes | 0 | 1 |  |  |  | RC 2 | Metallbau-, Schlosserarbeiten | 0 | E00 | 3.1 | Türmakro | SMT | TA-1F-AG-D-2S-O | MainObject | SmartPartCompressed | 100 | 7.21 | - | - | - | - | 1.05 | ja | - | - | - | - | 0 | 0.000000 | TA-1FL-D-2S-E00-004 | - | 2.05 | - | - | - | - | - | - | - | - | - | PZ | - | 0 | - | - | BS | Door | 1115Rau0000005181 | 1105Mak0811567302 | St | 6 |  |  |  |  |  |  |  |  |  |  |  |  |  |  |  |  |  |  | U23 | AllplanAttributes (SMT) - ash T_Unterschnitt: -; ash T_Material Oberlicht: -; ash D_Detailverweis: Typ4; g-Wert: 0,51; ash D_Plannummer: D1755; Pset_DoorCommon - AcousticRating: 32; Reference: T_Typ4
SMT | H2 Ebene 0 | 2.46 | 1.6825 | TI-2F-AG-D-O | 2.7722 | 200 | 200 | 100 | 100 | NEW | no | EI2 30 | 0 | no | yes | yes | SA | Metallbau-, Schlosserarbeiten | 0 | E00 | 3.1 | Türmakro | SMT | TI-2F-AG-D-O | MainObject | SmartPartCompressed | 100 | 7.21 | - | N | BZ | OTS | 0 | ja | - | FWS | EMF | - | 0 | 0.000000 | E00-F05-002-40 | L | 0 | SB | A | - | - | - | - | S | S | E | PZ(v) | KD | 1 | - | - | BS | Door | 1115Rau0000005065 | 1113Mak0814018057 | St | 40 | no | - | Stahl-Glas-Tür | E, H | Typ | 0 | 3.1 | TGR-Makro | PlanNo. | TGR 1.5 | MainObject | SmartPartCompressed | 8.9375 | 1.5 | 2 | 1115Rau0000005053 | 1113Mak0813533490 | St | S68 | AllplanAttributes (SMT) - ash T_Material Oberlicht: -; ash D_Detailverweis: D9; Text2: -; ash T_Steuerung (BG): E, H; ash D_Plannummer: 1684; Text3: Handauslösetaster vorrichten; AllplanAttributes (TGR 1.5) - OKFF: 0; Positionsnummer_Text: S68
SMT | H2 Ebene 0 | 2.46 | 1.9715 | TI-2F-AG-D-O | 3.20964 | 200 | 200 | 100 | 100 |  |  | EI2 30 | 0 | no | yes | no | SA |  | 0 | E00 | 3.1 | Türmakro, -SmartPart | SMT | TI-2F-AG-D-O | MainObject | SmartPartCompressed | 100 | 7.21 | - | - | BZ | OTS | 0 | ja | - | FWS | EMF | - | 0 | 0.000000 | E00-F03-001-69 | L | 0 | SB | - | - | - |  | - | S | S | E | PZ(v) | KD | 1 | - | - | BS | Door | 1115Rau0000005181 | 1113Mak0814009655 | St | 69 | no | - | Stahl-Glas-Tür | E, H | Typ | 0 | 3.1 | TGR-Makro | PlanNo. | TGR 1.5 | MainObject | SmartPartCompressed | 9.2265 | 1.5 | 2 | 1115Rau0000005053 | 1113Mak0813538837 | St | S68 | AllplanAttributes (TGR 1.5) - OKFF: 0; Positionsnummer_Text: S68; AllplanAttributes (SMT) - Text2: -; ash T_Steuerung (BG): E, H; Text3: Handauslösetaster vorrichten
SMT | H2 Ebene 0 | 2.46 | 1.968 | TI-1F-SG-D-M | 3.20232 | 200 | 200 | 100 | 100 | NEW | no | EI2 30 | 0 | no | yes | yes | SA | Zimmer- und Holzbauarbeiten | 0 | E00 | 3.0 | Türmakro, -SmartPart | SMT | TI-1F-SG-D-M | MainObject | SmartPartCompressed | 100 | 8.11 | - | N | BZ | OTS | 0 | ja | - | FWS | EMF | ZK | 0 | 0.000000 | E00-F07-001-94a | L | 0 | SB | A | - | - | TÖ + FTÖ | - | S | S | E | PZ(v) | KD | 1 | - | - | BGS | Door | 1113Tür0812508939 | 1113Mak0813945804 | St | 94a | no | - | Stahl-Glas-Tür | B, E | Typ | 0 | 3.1 | TGR-Makro | PlanNo. | TGR 1.5 | MainObject | SmartPartCompressed | 9.223 | 1.5 | 2 | 1113Tür0812508939 | 1113Mak0813519583 | St | S68 | Pset_DoorCommon - AcousticRating: 0; Reference: Codetext; AllplanAttributes (TGR 1.5) - OKFF: 0; Positionsnummer_Text: S68; AllplanAttributes (SMT) - Text2: X; ash T_Steuerung (BG): E; Codetext: Codetext; Funktion: Flurtür; Tragendes Bauteil: yes; Typ: 0; Brennbares Material: no; Brandverhalten: 0; Brandabschnittsdefinierendes Bauteil: no; Brandschutzklasse: A; Text3: Schlüsselschalter neben Tür
SMT | H2 Ebene 0 | 2.46 | 1.9715 | TI-2F-AG-D-O | 3.20964 | 200 | 200 | 100 | 100 |  |  | EI2 30 | 0 | no | yes | yes | SA |  | 0 | E00 | 3.1 | Türmakro, -SmartPart | SMT | TI-2F-AG-D-O | MainObject | SmartPartCompressed | 100 | 7.21 | - | - | BZ | OTS | 0 | ja | - | FWS | EMF | - | 0 | 0.000000 | E00-F07-001-105 | L | 0 | SB | A | - | - |  | - | S | S | E | PZ(v) | KD | 1 | - | - | BS | Door | 1115Rau0000005220 | 1113Mak0814014677 | St | 105 | no | - | Stahl-Glas-Tür | E, H | Typ | 0 | 3.1 | TGR-Makro | PlanNo. | TGR 1.5 | MainObject | SmartPartCompressed | 9.2265 | 1.5 | 2 | 1115Rau0000005053 | 1113Mak0813519956 | St | S68 | AllplanAttributes (TGR 1.5) - OKFF: 0; Positionsnummer_Text: S68; AllplanAttributes (SMT) - Text2: -; ash T_Steuerung (BG): E, H; Text3: Handauslösetaster vorrichten
SMT | H2 Ebene 0 | 2.46 | 2.55 | TI-1F-AG-D-1S-O | 4.19889 | 200 | 0 | 50 | 50 | NEW | no | EI2 30 | 0 | yes | yes | no |  | Zimmer- und Holzbauarbeiten | 0 | E00 | 3.0 | Türmakro | SMT | TI-1F-AG-D-1S-O | MainObject | SmartPartCompressed | 100 | 8.11 | - | - | BZ | OTS | 0 | ja | - | - | - |  | 0 | 0.000000 | E00-055-001-95 | L | 0 | SB | - | - | - | - | - | S | S | - | PZ | DD | 0 | - | - | BS | Door | 1116Rau0000065729 | 1113Mak0813949770 | St | 95 | no |  | Stahl-Glas-Tür |  | Typ | 0 | 3.1 | TGR-Makro | PlanNo. | TGR 1.5 | MainObject | SmartPartCompressed | 9.805 | 1.5 | 6 | 1115Rau0000005053 | 1113Mak0813987915 | St | S68 | AllplanAttributes (TGR 1.5) - OKFF: 0; Positionsnummer_Text: S68
SMT | H2 Ebene 0 | 2.7 | 1.355 | TI-1F-AG-D | 2.1006 | 200 | 100 | 0 | 0 | NEW | no | EI2 60 | 0 | no | yes | no | SA | Zimmer- und Holzbauarbeiten | 0 | E00 | 3.1 | Türmakro, -SmartPart | SMT | TI-1F-AG-D | MainObject | SmartPartCompressed | 100 | 7.21 | - | - | BZ | OTS | 0 | ja | - | - | EMF | - | 0 | 0.000000 | E00-013-001-165 | L | 0 | - | - | - | Ja |  | - | S | S | E | PZ | DD | 1 | - | - | BS | Door | 1116Rau0000066600 | 1113Mak0814179573 | St | 165 | no | - | Stahl-Glas-Tür | E | Typ | 0 | 3.1 | TGR-Makro | PlanNo. | TGR 1.5 | MainObject | SmartPartCompressed | 8.61 | 1.5 | 2 | 1116Rau0000066600 | 1113Mak0813535968 | St | S68 | AllplanAttributes (SMT) - ash D_Detailverweis: D3; ash D_Plannummer: 1684; AllplanAttributes (TGR 1.5) - OKFF: 0; Positionsnummer_Text: S68
SMT | H2 Ebene 0 | 2.46 | 2.55 | TI-1F-AG-D-1S-O | 4.08729 | 200 | 0 | 50 | 50 |  |  | EI2 60 | 0 | yes | yes | no |  | Zimmer- und Holzbauarbeiten | 0 | E00 | 3.0 | Türmakro, -SmartPart | SMT | TI-1F-AG-D-1S-O | MainObject | SmartPartCompressed | 100 | 8.11 | - | - | BZ | OTS | 0 | ja | - | - | - | - | 0 | 0.000000 | E00-008-001-80 | L | 0 | SB | - | - | - | - | - | S | S | - | PZ | DD | 0 | - | - | BS | Door | 1116Rau0000065732 | 1113Mak0813911702 | St | 80 | no | - | Stahl-Glas-Tür |  | Typ | 0 | 3.1 | TGR-Makro | PlanNo. | TGR 1.5 | MainObject | SmartPartCompressed | 9.805 | 1.5 | 8 | 1115Rau0000005053 | 1113Mak0813958205 | St | S68 | AllplanAttributes (TGR 1.5) - OKFF: 0; Positionsnummer_Text: S68
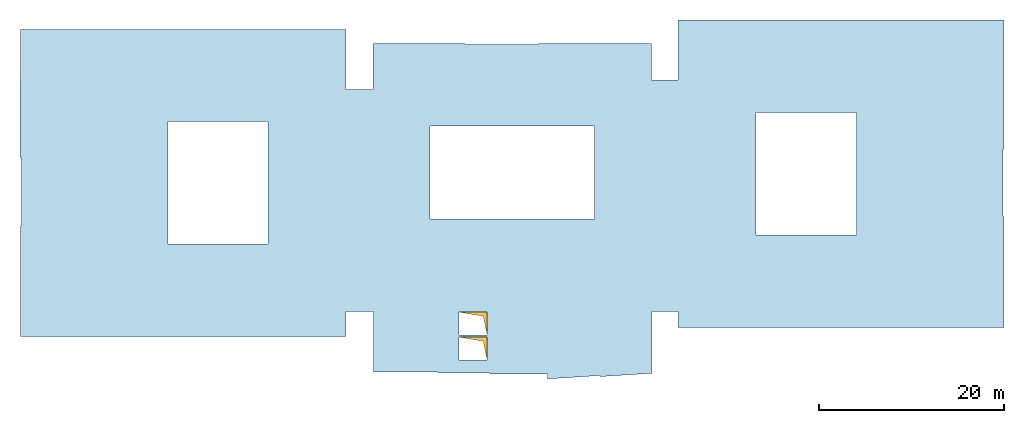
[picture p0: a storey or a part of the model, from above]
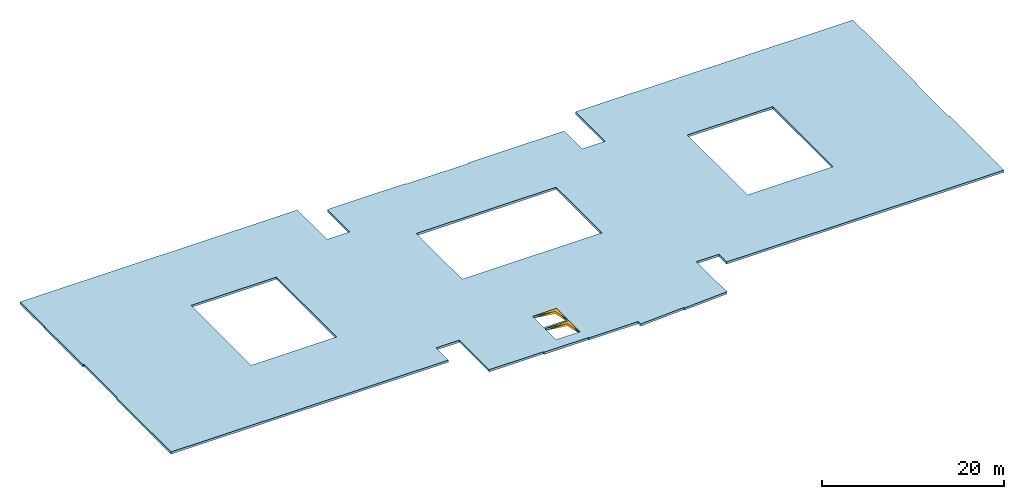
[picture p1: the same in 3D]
Properties of the parts of a building model (IFC4), part 24 of 80

# IfcDoor (58)
Name | In | OverallHeight (m) | OverallWidth (m) | Material | GlassSurface | OffsetOpeningBottom | DeductionOpeningBottom | DeductionOpeningLeft = DeductionOpeningRight | DeductionOpeningTop | Status | IsExternal | FireRating | ThermalTransmittance (W/K/m2) | HandicapAccessible | SmokeStop = SelfClosing | FireExit | SecurityRating | AllplanAttributes (SMT), Gewerk | AllplanAttributes (SMT), V6 (m) = AllplanAttributes (SMT), V7 (m) = AllplanAttributes (SMT), V8 (m) = AllplanAttributes (SMT), V9 = AllplanAttributes (SMT), ash T_Lüftungsgitter (m2) = AllplanAttributes (SMT), ash T_Anz_Reedkontakte | AllplanAttributes (SMT), Ortscode_Geschoßbezeichnung | AllplanAttributes (SMT), Programmversion | AllplanAttributes (SMT), Objektname | AllplanAttributes (SMT), Bezeichnung | AllplanAttributes (SMT), Material | AllplanAttributes (SMT), Plugin_Bezeichnung | AllplanAttributes (SMT), Plugin_Objektname | AllplanAttributes (SMT), Glasanteil_berücksichtigen | AllplanAttributes (SMT), Version | AllplanAttributes (SMT), ash T_Sichtschutz = AllplanAttributes (SMT), ash R_Verweis Wandansicht = AllplanAttributes (SMT), ash T_Gewerk Los = AllplanAttributes (SMT), ash T_Standflügel-Betätigung = AllplanAttributes (SMT), ash T_Zusatzfunktion Türschließer = AllplanAttributes (SMT), ash T_Türschließer-Montage = AllplanAttributes (SMT), ash T_Zusätzliche Rauchmelder = AllplanAttributes (SMT), ash T_Zusätzl. Anschluss an BMA = AllplanAttributes (SMT), ash T_Impulsgeber = AllplanAttributes (SMT), ash T_Sicherheits-Sensorleisten = AllplanAttributes (SMT), ash T_Anschl. an Einbruchmeld.anl. = AllplanAttributes (SMT), ash T_Klemmschutz = AllplanAttributes (SMT), ash T_LV-Positions-Nr. = AllplanAttributes (SMT), ash T_Plan-Nr. = AllplanAttributes (SMT), ash T_Sonstiges, Bemerkungen = AllplanAttributes (SMT), ash T_Bodentürstopper = AllplanAttributes (SMT), ash T_Material Seitenteil = AllplanAttributes (SMT), ash T_Kantengeometrie = AllplanAttributes (SMT), ash T_Kantenmaterial = AllplanAttributes (SMT), ash T_Feuchtebeständigkeit = AllplanAttributes (SMT), ash T_Glasausschnitt = AllplanAttributes (SMT), ash T_Sonder_Wandmaterial = AllplanAttributes (SMT), ash T_Bodeneinstand = AllplanAttributes (SMT), ash T_Blatt_Farbe | AllplanAttributes (SMT), ash T_Panik | AllplanAttributes (SMT), ash T_Zarge_Typ | AllplanAttributes (SMT), ash T_Türschließer | AllplanAttributes (SMT), ash T_Erforderl. Durchgangsbreite (m) | AllplanAttributes (SMT), ash T_Türblatt sichtbar 2D | AllplanAttributes (SMT), ash T_Zusatzfunktion Panikschloss | AllplanAttributes (SMT), ash T_Fluchtwegsicherung | AllplanAttributes (SMT), ash T_Feststellanlage (FSA) | AllplanAttributes (SMT), ash T_Anschl. an Zuttrittskontrolle | AllplanAttributes (SMT), OKFF | AllplanAttributes (SMT), ash T_Strahlenschutz | AllplanAttributes (SMT), ash T_Tür-Nr. | AllplanAttributes (SMT), ash T_Blatt_Oberfläche | AllplanAttributes (SMT), ash T_Erford. Durgangshöhe (m) | AllplanAttributes (SMT), ash T_Rammschutz | AllplanAttributes (SMT), ash T_Fluchtwegrichtung | AllplanAttributes (SMT), ash T_Anschlag Gangflügel | AllplanAttributes (SMT), ash T_Bodendichtung | AllplanAttributes (SMT), ash T_E_Öffner | AllplanAttributes (SMT), ash T_Automatik_Antrieb | AllplanAttributes (SMT), ash T_Sturz | AllplanAttributes (SMT), ash T_Blatt_Material | AllplanAttributes (SMT), ash T_Schlossfunktion | AllplanAttributes (SMT), ash T_Schliesszylinder | AllplanAttributes (SMT), ash T_Beschlag | AllplanAttributes (SMT), ash T_Anz_Riegelkontakte | AllplanAttributes (SMT), ash T_Schallschutz | AllplanAttributes (SMT), ash T_Zarge_Material | AllplanAttributes (SMT), ash T_Raum zugehörigkeit | AllplanAttributes (SMT), Attributset-Objekt | AllplanAttributes (SMT), P_ID | AllplanAttributes (SMT), Allright_Bauteil_ID | AllplanAttributes (SMT), Abrechnungsart | AllplanAttributes (SMT), Text1 | AllplanAttributes (SMT), ash T_Zulage Schachttür = AllplanAttributes (SMT), ash T_Dichtschließend = AllplanAttributes (SMT), ash T_nicht abschließbar | AllplanAttributes (SMT), ash T_Laserschutz | Text4 | ash T_Steuerung (BS) | AllplanAttributes (TGR 1.5), Codetext | AllplanAttributes (TGR 1.5), V6 (m) = AllplanAttributes (TGR 1.5), V7 (m) = AllplanAttributes (TGR 1.5), V8 (m) = AllplanAttributes (TGR 1.5), V9 | AllplanAttributes (TGR 1.5), Programmversion | AllplanAttributes (TGR 1.5), Objektname | AllplanAttributes (TGR 1.5), Text1 | AllplanAttributes (TGR 1.5), Bezeichnung | AllplanAttributes (TGR 1.5), Plugin_Bezeichnung | AllplanAttributes (TGR 1.5), Plugin_Objektname | AllplanAttributes (TGR 1.5), Gesamtlänge | AllplanAttributes (TGR 1.5), Version | AllplanAttributes (TGR 1.5), ash T_Türprofilnummer | AllplanAttributes (TGR 1.5), P_ID | AllplanAttributes (TGR 1.5), Allright_Bauteil_ID | AllplanAttributes (TGR 1.5), Abrechnungsart | AllplanAttributes (SMT), Positionsnummer_Text
SMT | H2 Ebene 0 | 2.46 | 2.063 | TI-1F-SG-D-M | 3.40087 | 200 | 200 | 100 | 100 | NEW | no | EI2 30 | 0 | no | yes | yes | SA | Zimmer- und Holzbauarbeiten | 0 | E00 | 3.0 | Türmakro, -SmartPart | SMT | TI-1F-SG-D-M | MainObject | SmartPartCompressed | 100 | 8.11 | - | N | BZ | OTS | 0 | ja | - | FWS | EMF | ZK | 0 | 0.000000 | E00-F03-001-94 | L | 0 | SB | A | - | - | TÖ + FTÖ | - | S | S | E | PZ(v) | KD | 1 | - | - | BGS | Door | 1115Rau0000005053 | 1113Mak0813912773 | St | 94 | no | - | Stahl-Glas-Tür | B, E | Typ | 0 | 3.1 | TGR-Makro | PlanNo. | TGR 1.5 | MainObject | SmartPartCompressed | 9.318 | 1.5 | 6 | 1115Rau0000005053 | 1113Mak0813417856 | St | S68 | AllplanAttributes (SMT) - ash D_Detailverweis: D1; Text2: X; ash T_Steuerung (BG): E; Codetext: Codetext; Funktion: Flurtür; Tragendes Bauteil: yes; Typ: 0; Brennbares Material: no; Brandverhalten: 0; Brandabschnittsdefinierendes Bauteil: no; Brandschutzklasse: A; ash D_Plannummer: 1684; Text3: Schlüsselschalter neben Tür; Pset_DoorCommon - AcousticRating: 0; Reference: Codetext; AllplanAttributes (TGR 1.5) - OKFF: 0; Positionsnummer_Text: S68
SMT | H2 Ebene 0 | 2.46 | 1.94163 | TI-1F-SG-D-M | 3.14721 | 200 | 200 | 100 | 100 | NEW | no | EI2 30 | 0 | no | yes | yes | SA | Zimmer- und Holzbauarbeiten | 0 | E00 | 3.1 | Türmakro, -SmartPart | SMT | TI-1F-SG-D-M | MainObject | SmartPartCompressed | 100 | 7.21 | - | N | BZ | - | 0 | ja | - | FWS | - | ZK | 0 | 0.000000 | E00-F07-001-162 | L | 0 | SB | A | - | - | TÖ + FTÖ | M1 | S | S | E | PZ(v) | KD | 1 | - | - | BGS | Door | 1115Rau0000005189 | 1113Mak0813913800 | St | 162 | no | - | Stahl-Glas-Tür | E, G | Typ | 0 | 3.1 | TGR-Makro | PlanNo. | TGR 1.5 | MainObject | SmartPartCompressed | 9.19663 | 1.5 | 6 | 1115Rau0000005189 | 1113Mak0813496481 | St | S68 | Pset_DoorCommon - AcousticRating: 0; Reference: Codetext; AllplanAttributes (TGR 1.5) - OKFF: 0; Positionsnummer_Text: S68; AllplanAttributes (SMT) - Text2: X; ash T_Steuerung (BG): B, C, E; Codetext: Codetext; Funktion: Flurtür; Tragendes Bauteil: yes; Typ: 0; Brennbares Material: no; Brandverhalten: 0; Brandabschnittsdefinierendes Bauteil: no; Brandschutzklasse: A; Text3: Schlüsselschalter neben Tür
SMT | H2 Ebene 0 | 2.46 | 3.667 | TI-1F-AG-S | 6.75018 | 200 | 0 | 50 | 50 | NEW | no |  | 0 | no | no | no |  | Metallbau-, Schlosserarbeiten | 0 | E00 | 3.1 | Türmakro | SMT | TI-1F-AG-S | MainObject | SmartPartCompressed | 100 | 7.21 | - | - | - | - | 0 | ja | - | - | - |  | 0 | 0.000000 | E00-050-002-92 | L | 0 | - | - | - | - | - | - | - | SG | - | PZ | DD | 0 | - | - | BGS | Door | 1116Rau0000065729 | 1113Mak0813017188 | St | 92 | no | - |  |  |  |  |  |  |  |  |  |  |  |  |  |  |  |  | S68 | AllplanAttributes (SMT) - ash T_Unterschnitt: 1; AllplanAttributes (TGR 1.6) - Codetext: Typ; V6: 0 m; V7: 0 m; V8: 0 m; V9: 0; Programmversion: 3.1; Objektname: TGR-Makro; Text1: PlanNo.; Bezeichnung: TGR 1.6; Plugin_Bezeichnung: MainObject; Plugin_Objektname: SmartPartCompressed; Gesamtlänge: 10.867; Version: 1.6; OKFF: 0; ash T_Türprofilnummer: 2; Allright_Bauteil_ID: 1113Mak0813575644; Abrechnungsart: St; Positionsnummer_Text: S68
SMT | H2 Ebene 0 | 2.46 | 3.64 | TI-1F-AG-S | 6.69537 | 200 | 0 | 50 | 50 | NEW | no |  | 0 | no | no | no |  | Metallbau-, Schlosserarbeiten | 0 | E00 | 3.1 | Türmakro | SMT | TI-1F-AG-S | MainObject | SmartPartCompressed | 100 | 7.21 | - | - | - | - | 0 | ja | - | - | - |  | 0 | 0.000000 | E00-048-002-85 | L | 0 | - | - | - | - | - | - | - | SG | - | PZ | DD | 0 | - | - | BGS | Door | 1116Rau0000065732 | 1113Mak0813911357 | St | 85 | no | - |  |  |  |  |  |  |  |  |  |  |  |  |  |  |  |  | S68 | AllplanAttributes (SMT) - ash T_Unterschnitt: 1; AllplanAttributes (TGR 1.6) - Codetext: Typ; V6: 0 m; V7: 0 m; V8: 0 m; V9: 0; Programmversion: 3.1; Objektname: TGR-Makro; Text1: PlanNo.; Bezeichnung: TGR 1.6; Plugin_Bezeichnung: MainObject; Plugin_Objektname: SmartPartCompressed; Gesamtlänge: 10.84; Version: 1.6; OKFF: 0; ash T_Türprofilnummer: 2; Allright_Bauteil_ID: 1113Mak0813575408; Abrechnungsart: St; Positionsnummer_Text: S68
FS-Vorhang | H2 Ebene 0 | 2.62 | 1.84 | TI-1F-UZ-M-ZK | 0 | 200 | 200 | 120 | 0 | NEW | no | EW 60 | 0 | no | yes | no | - | AllplanAttributes (FS-Vorhang) - Gewerk: Zimmer- und Holzbauarbeiten; V6: 0 m; V7: 0 m; V8: 0 m; V9: 0; Ortscode_Geschoßbezeichnung: E00; Programmversion: 3.1; Objektname: Brandschutzvorhang; Text1: S200 C2; Bezeichnung: FS-Vorhang; Material: TI-1F-UZ-M-ZK; Plugin_Bezeichnung: MainObject; Plugin_Objektname: SmartPartCompressed; Glasanteil_berücksichtigen: 100; Version: 7.21; ash T_Sichtschutz: -; ash R_Verweis Wandansicht: -; ash T_Zulage Schachttür: no; ash T_Dichtschließend: no; ash T_Panik: -; ash T_Zarge_Typ: U; ash T_Türschließer: -; ash T_Gewerk Los: -; ash T_Erforderl. Durchgangsbreite: 0 m; ash T_Türblatt sichtbar 2D: ja; ash T_Zusatzfunktion Panikschloss: -; ash T_Fluchtwegsicherung: -; ash T_Standflügel-Betätigung: -; ash T_Zusatzfunktion Türschließer: -; ash T_Türschließer-Montage: -; ash T_Feststellanlage (FSA): -; ash T_Zusätzliche Rauchmelder: -; ash T_Zusätzl. Anschluss an BMA: -; ash T_Impulsgeber: -; ash T_Sicherheits-Sensorleisten: -; ash T_Anschl. an Zuttrittskontrolle: -; ash T_Anschl. an Einbruchmeld.anl.: -; ash T_Klemmschutz: -; ash T_LV-Positions-Nr.: -; ash T_Plan-Nr.: -; ash T_Sonstiges, Bemerkungen: -; OKFF: 0; ash T_Bodentürstopper: -; ash T_nicht abschließbar: no; ash T_Material Seitenteil: -; ash T_Strahlenschutz: 0.000000; ash T_Tür-Nr.: FS-Vorhang; ash T_Kantengeometrie: -; ash T_Kantenmaterial: -; ash T_Blatt_Oberfläche: L; ash T_Erford. Durgangshöhe: 0 m; ash T_Laserschutz: -; ash T_Rammschutz: -; ash T_Fluchtwegrichtung: -; ash T_Anschlag Gangflügel: -; ash T_Bodendichtung: -; ash T_Lüftungsgitter: 0 m2; ash T_Feuchtebeständigkeit: -; ash T_E_Öffner: -; ash T_Automatik_Antrieb: -; ash T_Sturz: -; ash T_Blatt_Material: AL; ash T_Schlossfunktion: -; ash T_Schliesszylinder: -; ash T_Beschlag: -; ash T_Material Oberlicht: -; ash T_Glasausschnitt: -; ash T_Sonder_Wandmaterial: -; ash T_Anz_Reedkontakte: 0; ash T_Anz_Riegelkontakte: 0; ash T_Schallschutz: -; ash T_Zarge_Material: S; ash T_Bodeneinstand: -; ash T_Raum zugehörigkeit: BS; ash T_Blatt_Farbe: -; Attributset-Objekt: Door; P_ID: 1115Rau0000005163; Allright_Bauteil_ID: 1113Mak0813934237; Abrechnungsart: St
FS-Vorhang | H2 Ebene 0 | 2.62 | 1.84 | TI-1F-UZ-M-ZK | 0 | 200 | 200 | 120 | 0 | NEW | no | EW 60 | 0 | no | yes | no | - | AllplanAttributes (FS-Vorhang) - Gewerk: Zimmer- und Holzbauarbeiten; V6: 0 m; V7: 0 m; V8: 0 m; V9: 0; Ortscode_Geschoßbezeichnung: E00; Programmversion: 3.1; Objektname: Brandschutzvorhang; Text1: S200 C2; Bezeichnung: FS-Vorhang; Material: TI-1F-UZ-M-ZK; Plugin_Bezeichnung: MainObject; Plugin_Objektname: SmartPartCompressed; Glasanteil_berücksichtigen: 100; Version: 7.21; ash T_Sichtschutz: -; ash R_Verweis Wandansicht: -; ash T_Zulage Schachttür: no; ash T_Dichtschließend: no; ash T_Panik: -; ash T_Zarge_Typ: U; ash T_Türschließer: -; ash T_Gewerk Los: -; ash T_Erforderl. Durchgangsbreite: 0 m; ash T_Türblatt sichtbar 2D: ja; ash T_Zusatzfunktion Panikschloss: -; ash T_Fluchtwegsicherung: -; ash T_Standflügel-Betätigung: -; ash T_Zusatzfunktion Türschließer: -; ash T_Türschließer-Montage: -; ash T_Feststellanlage (FSA): -; ash T_Zusätzliche Rauchmelder: -; ash T_Zusätzl. Anschluss an BMA: -; ash T_Impulsgeber: -; ash T_Sicherheits-Sensorleisten: -; ash T_Anschl. an Zuttrittskontrolle: -; ash T_Anschl. an Einbruchmeld.anl.: -; ash T_Klemmschutz: -; ash T_LV-Positions-Nr.: -; ash T_Plan-Nr.: -; ash T_Sonstiges, Bemerkungen: -; OKFF: 0; ash T_Bodentürstopper: -; ash T_nicht abschließbar: no; ash T_Material Seitenteil: -; ash T_Strahlenschutz: 0.000000; ash T_Tür-Nr.: FS-Vorhang; ash T_Kantengeometrie: -; ash T_Kantenmaterial: -; ash T_Blatt_Oberfläche: L; ash T_Erford. Durgangshöhe: 0 m; ash T_Laserschutz: -; ash T_Rammschutz: -; ash T_Fluchtwegrichtung: -; ash T_Anschlag Gangflügel: -; ash T_Bodendichtung: -; ash T_Lüftungsgitter: 0 m2; ash T_Feuchtebeständigkeit: -; ash T_E_Öffner: -; ash T_Automatik_Antrieb: -; ash T_Sturz: -; ash T_Blatt_Material: AL; ash T_Schlossfunktion: -; ash T_Schliesszylinder: -; ash T_Beschlag: -; ash T_Material Oberlicht: -; ash T_Glasausschnitt: -; ash T_Sonder_Wandmaterial: -; ash T_Anz_Reedkontakte: 0; ash T_Anz_Riegelkontakte: 0; ash T_Schallschutz: -; ash T_Zarge_Material: S; ash T_Bodeneinstand: -; ash T_Raum zugehörigkeit: BS; ash T_Blatt_Farbe: -; Attributset-Objekt: Door; P_ID: 1115Rau0000005163; Allright_Bauteil_ID: 1113Mak0813937093; Abrechnungsart: St
SMT | H2 Ebene 0 | 2.46 | 1.97125 | TI-2F-AG-D-O | 3.20911 | 200 | 200 | 100 | 100 | NEW | no | EI2 30 | 0 | no | yes | yes | SA | Betonarbeiten | 0 | E00 | 3.1 | Türmakro, -SmartPart | SMT | TI-2F-AG-D-O | MainObject | SmartPartCompressed | 100 | 7.21 | - | N | BZ | OTS | 0 | ja | - | FWS | EMF | - | 0 | 0.000000 | E00-F03-002-22 | L | 0 | SB | A | - | - | - | - | S | S | E | PZ(v) | KD | 1 | - | - | BS | Door | 1115Rau0000005181 | 1113Mak0813959620 | St | 22 | no | - | Stahl-Glas-Tür | E, H | Typ | 0 | 3.1 | TGR-Makro | PlanNo. | TGR 1.5 | MainObject | SmartPartCompressed | 9.22625 | 1.5 | 2 | 1115Rau0000005053 | 1113Mak0813870035 | St | S68 | AllplanAttributes (SMT) - ash T_Material Oberlicht: -; Text2: -; ash T_Steuerung (BG): E, H; Codetext: Codetext; Funktion: Flurtür; Tragendes Bauteil: yes; Typ: 0; Brennbares Material: no; Brandverhalten: 0; Brandabschnittsdefinierendes Bauteil: no; Brandschutzklasse: A; Text3: Handauslösetaster vorrichten; Pset_DoorCommon - AcousticRating: 0; Reference: Codetext; AllplanAttributes (TGR 1.5) - OKFF: 0; Positionsnummer_Text: S68
SMT | H2 Ebene 0 | 2.46 | 1.965 | TI-2F-AG-D-O | 3.19605 | 200 | 200 | 100 | 100 | NEW | no | EI2 30 | 0 | no | yes | yes | SA | Betonarbeiten | 0 | E00 | 3.1 | Türmakro, -SmartPart | SMT | TI-2F-AG-D-O | MainObject | SmartPartCompressed | 100 | 7.21 | - | N | BZ | OTS | 0 | ja | - | FWS | EMF | - | 0 | 0.000000 | E00-F07-001-153 | L | 0 | SB | A | - | - |  | - | S | S | E | PZ(v) | KD | 1 | - | - | BS | Door | 1115Rau0000005220 | 1113Mak0813959363 | St | 153 | no | - | Stahl-Glas-Tür | E, H | Typ | 0 | 3.1 | TGR-Makro | PlanNo. | TGR 1.5 | MainObject | SmartPartCompressed | 9.22 | 1.5 | 2 | 1115Rau0000005053 | 1113Mak0813536359 | St | S68 | Pset_DoorCommon - AcousticRating: 0; Reference: Codetext; AllplanAttributes (TGR 1.5) - OKFF: 0; Positionsnummer_Text: S68; AllplanAttributes (SMT) - Text2: -; ash T_Steuerung (BG): E, H; Codetext: Codetext; Funktion: Flurtür; Tragendes Bauteil: yes; Typ: 0; Brennbares Material: no; Brandverhalten: 0; Brandabschnittsdefinierendes Bauteil: no; Brandschutzklasse: A; Text3: Handauslösetaster vorrichten
SMT | H2 Ebene 0 | 2.58 | 2.3 | TI-1F-AG-D-1S-ZK | 4.00309 | 200 | 100 | 0 | 0 | NEW | no | EI2 30 | 0 | no | yes | yes |  | Zimmer- und Holzbauarbeiten | 0 | E00 | 3.1 | Türmakro | SMT | TI-1F-AG-D-1S-ZK | MainObject | SmartPartCompressed | 100 | 7.21 | - | N | BZ | OTS | 0 | ja | - | FWS | - | ZK | 0 | 0.000000 | E00-T03-001-88 | L | 0 | SB | A | - | - | TÖ + FTÖ | - |  | S | E | PZ(v) | KD | 1 | - | - | BGS | Door | 1115Rau0000005053 | 1113Mak0812437060 | St | 88 | no | - | Stahl-Glas-Tür | E, H |  |  |  |  |  |  |  |  |  |  |  |  |  |  | S68 | AllplanAttributes (SMT) - Text2: X; ash T_Steuerung (BG): E, H

# IfcDoor (2)
In: H2 Ebene +3
Type - PredefinedType: DOOR; OperationType: SINGLE_SWING_LEFT; ParameterTakesPrecedence: no
Type - IfcDoorLiningProperties - LiningDepth: 0.262 m; LiningThickness: 0.02 m
OverallHeight: 2.41 m; OverallWidth: 1.01 m; Material: TI-1F-UZ-D
AllplanAttributes (1) - Gewerk: Metallbau-, Schlosserarbeiten; V6: 0 m; V7: 0 m; V8: 0 m; V9: 0; Programmversion: 3.0; Objektname: Türmakro; Text2: -; Material: TI-1F-UZ-D; Plugin_Bezeichnung: MainObject; Plugin_Objektname: SmartPartCompressed; Glasanteil_berücksichtigen: 100; Version: 9.62; ash T_Unterschnitt: -; ash T_Panik: -; ash T_Zarge_Typ: UZ; ash T_Türschließer: -; ash T_Erforderl. Durchgangsbreite: 0 m; ash T_Türblatt sichtbar 2D: ja; ash T_Zusatzfunktion Panikschloss: -; ash T_Fluchtwegsicherung: -; ash T_Standflügel-Betätigung: -; ash T_Zusatzfunktion Türschließer: -; ash T_Türschließer-Montage: -; ash T_Zusätzliche Rauchmelder: -; ash T_Zusätzl. Anschluss an BMA: -; ash T_Impulsgeber: -; ash T_Sicherheits-Sensorleisten: -; ash T_Anschl. an Zuttrittskontrolle: -; ash T_Anschl. an Einbruchmeld.anl.: -; ash T_Klemmschutz: -; OKFF: 11.25; ash T_Bodentürstopper: -; ash T_Strahlenschutz: 0.000000; ash T_Kantengeometrie: LF; ash T_Kantenmaterial: -; ash T_Blatt_Oberfläche: L; ash T_Erford. Durgangshöhe: 0 m; ash T_Laserschutz: -; ash T_Rammschutz: -; ash T_Fluchtwegrichtung: -; ash T_Anschlag Gangflügel: -; ash T_Bodendichtung: -; ash T_Lüftungsgitter: 0 m2; ash T_Feuchtebeständigkeit: -; ash T_E_Öffner: -; ash T_Automatik_Antrieb: -; ash T_Sturz: -; ash T_Blatt_Material: ST; ash T_Schliesszylinder: PZ; ash T_Beschlag: KD; ash T_Anz_Reedkontakte: 0; ash T_Anz_Riegelkontakte: 0; ash T_Schallschutz: -; ash T_Zarge_Material: ST; ash T_Bodeneinstand: -; ash T_Raum zugehörigkeit: BGS; Attributset-Objekt: Door; P_ID: 1265Rau0000000023; Abrechnungsart: St
AllplanQuantities - GlassSurface: 0; HeightWindowSillOutside: 0; HeightWindowSillInside: 0; OffsetOpeningBottom: 150; OffsetOpeningTop: 0; OffsetOpeningLeft: 0; OffsetOpeningRight: 0; DeductionOpeningBottom: 100; DeductionOpeningLeft: 20; DeductionOpeningRight: 20; DeductionOpeningTop: 20
Pset_DoorCommon - Status: NEW; IsExternal: no; ThermalTransmittance: 0 W/K/m2; HandicapAccessible: no; FireExit: no; SecurityRating: SA
Name | Text1 | ash T_Tür-Nr. | Allright_Bauteil_ID
 | 34 | E03-F02-001-34 | 1263Mak0812820192
 | 34b | E03-F02-001-34b | 1263Mak0812995421

# IfcDoor: Revisionstür
In: H2 Ebene +3
Type - PredefinedType: DOOR; OperationType: SINGLE_SWING_RIGHT; ParameterTakesPrecedence: no
Type - IfcDoorLiningProperties - LiningDepth: 0.32 m; LiningThickness: 0.02 m
OverallHeight: 2.41 m; OverallWidth: 1.01 m; Material: TI-1F-UZ-D
AllplanAttributes (Revisionstür) - Gewerk: Metallbau-, Schlosserarbeiten; V6: 0 m; V7: 0 m; V8: 0 m; V9: 0; Programmversion: 3.0; Objektname: Türmakro; Text1: 44; Text2: -; Bezeichnung: Revisionstür; Material: TI-1F-UZ-D; Plugin_Bezeichnung: MainObject; Plugin_Objektname: SmartPartCompressed; Glasanteil_berücksichtigen: 100; Version: 9.62; ash T_Unterschnitt: -; ash T_Panik: -; ash T_Zarge_Typ: UZ; ash T_Türschließer: OTS; ash T_Erforderl. Durchgangsbreite: 0 m; ash T_Türblatt sichtbar 2D: ja; ash T_Zusatzfunktion Panikschloss: -; ash T_Fluchtwegsicherung: -; ash T_Standflügel-Betätigung: -; ash T_Zusatzfunktion Türschließer: -; ash T_Türschließer-Montage: -; ash T_Zusätzliche Rauchmelder: -; ash T_Zusätzl. Anschluss an BMA: -; ash T_Impulsgeber: -; ash T_Sicherheits-Sensorleisten: -; ash T_Anschl. an Zuttrittskontrolle: -; ash T_Anschl. an Einbruchmeld.anl.: -; ash T_Klemmschutz: -; OKFF: 11.25; ash T_Bodentürstopper: -; ash T_Strahlenschutz: 0.000000; ash T_Tür-Nr.: E03-F03-001-44; ash T_Kantengeometrie: LF; ash T_Kantenmaterial: -; ash T_Blatt_Oberfläche: L; ash T_Erford. Durgangshöhe: 0 m; ash T_Laserschutz: -; ash T_Rammschutz: -; ash T_Fluchtwegrichtung: -; ash T_Anschlag Gangflügel: -; ash T_Bodendichtung: -; ash T_Lüftungsgitter: 0 m2; ash T_Feuchtebeständigkeit: -; ash T_E_Öffner: -; ash T_Automatik_Antrieb: -; ash T_Sturz: -; ash T_Blatt_Material: ST; ash T_Schliesszylinder: PZ; ash T_Beschlag: KD; ash T_Anz_Reedkontakte: 0; ash T_Anz_Riegelkontakte: 0; ash T_Schallschutz: -; ash T_Zarge_Material: ST; ash T_Bodeneinstand: -; ash T_Raum zugehörigkeit: BS; Attributset-Objekt: Door; P_ID: 1265Rau0000000012; Allright_Bauteil_ID: 1263Mak0812819990; Abrechnungsart: St
AllplanQuantities - GlassSurface: 0; HeightWindowSillOutside: 0; HeightWindowSillInside: 0; OffsetOpeningBottom: 150; OffsetOpeningTop: 0; OffsetOpeningLeft: 0; OffsetOpeningRight: 0; DeductionOpeningBottom: 100; DeductionOpeningLeft: 20; DeductionOpeningRight: 20; DeductionOpeningTop: 20
Pset_DoorCommon - Status: NEW; IsExternal: no; FireRating: EI2 60; ThermalTransmittance: 0 W/K/m2; HandicapAccessible: no; SmokeStop: yes; SelfClosing: yes; FireExit: no; SecurityRating: SA

# IfcDoor: SMT (5)
In: H2 Ebene +3
Type - PredefinedType: DOOR; OperationType: DOUBLE_DOOR_SINGLE_SWING; ParameterTakesPrecedence: no
Type - IfcDoorLiningProperties - LiningDepth: 0.079 m; LiningThickness: 0.05 m
Material: TI-2F-AG-D-O
AllplanAttributes (SMT) - Gewerk: Metallbau-, Schlosserarbeiten; V6: 0 m; V7: 0 m; V8: 0 m; V9: 0; Ortscode_Geschoßbezeichnung: E03; Programmversion: 3.0; Objektname: Türmakro; Text2: -; Bezeichnung: SMT; Material: TI-2F-AG-D-O; Plugin_Bezeichnung: MainObject; Plugin_Objektname: SmartPartCompressed; Glasanteil_berücksichtigen: 100; Version: 8.11; ash T_Zulage Schachttür: no; ash T_Dichtschließend: no; ash T_Zarge_Typ: UZ; ash T_Türschließer: OTS; ash T_Erforderl. Durchgangsbreite: 0 m; ash T_Türblatt sichtbar 2D: ja; ash T_Feststellanlage (FSA): -; OKFF: 11.25; ash T_nicht abschließbar: no; ash T_Strahlenschutz: 0.000000; ash T_Kantengeometrie: LF; ash T_Blatt_Oberfläche: L; ash T_Erford. Durgangshöhe: 0 m; ash T_Anschlag Gangflügel: -; ash T_Lüftungsgitter: 0 m2; ash T_Blatt_Material: ST; ash T_Schliesszylinder: PZ; ash T_Anz_Reedkontakte: 0; ash T_Anz_Riegelkontakte: 0; ash T_Schallschutz: -; ash T_Zarge_Material: ST; Attributset-Objekt: Door; Abrechnungsart: St
AllplanAttributes (TGR 1.5) - Codetext: Typ; V6: 0 m; V7: 0 m; V8: 0 m; V9: 0; Programmversion: 3.1; Objektname: TGR-Makro; Text1: PlanNo.; Bezeichnung: TGR 1.5; Plugin_Bezeichnung: MainObject; Plugin_Objektname: SmartPartCompressed; Version: 1.5; OKFF: 11.25; Abrechnungsart: St
AllplanQuantities - HeightWindowSillOutside: 0; HeightWindowSillInside: 0; OffsetOpeningBottom: 150; OffsetOpeningTop: 0; OffsetOpeningLeft: 0; OffsetOpeningRight: 0; DeductionOpeningBottom: 100; DeductionOpeningLeft: 50; DeductionOpeningRight: 50; DeductionOpeningTop: 50
Pset_DoorCommon - Status: NEW; IsExternal: no; ThermalTransmittance: 0 W/K/m2; HandicapAccessible: no; SmokeStop: yes; SelfClosing: yes; FireExit: no
Name | OverallHeight (m) | OverallWidth (m) | Text1 | Text4 | ash T_Panik | ash T_Zusatzfunktion Panikschloss = ash T_Fluchtwegsicherung = ash T_Standflügel-Betätigung = ash T_Zusatzfunktion Türschließer = ash T_Türschließer-Montage = ash T_Zusätzliche Rauchmelder = ash T_Zusätzl. Anschluss an BMA = ash T_Impulsgeber = ash T_Sicherheits-Sensorleisten = ash T_Anschl. an Zuttrittskontrolle = ash T_Anschl. an Einbruchmeld.anl. = ash T_Klemmschutz = ash T_Bodentürstopper = ash T_Kantenmaterial = ash T_Laserschutz = ash T_Rammschutz = ash T_Fluchtwegrichtung = ash T_Bodendichtung = ash T_Feuchtebeständigkeit = ash T_E_Öffner = ash T_Automatik_Antrieb = ash T_Sturz = ash T_Material Oberlicht = ash T_Bodeneinstand | ash T_Tür-Nr. | ash T_Beschlag | ash T_Raum zugehörigkeit | AllplanAttributes (SMT), P_ID | AllplanAttributes (SMT), Allright_Bauteil_ID | Gesamtlänge | ash T_Türprofilnummer | AllplanAttributes (TGR 1.5), P_ID | AllplanAttributes (TGR 1.5), Allright_Bauteil_ID | GlassSurface | FireRating | SecurityRating
SMT | 2.9 | 2.0665 | 24 | Technik-Tür | - | - | E03-F01-001-24 | KD | BS | 1265Rau0000000034 | 1263Mak0812939737 | 8.9215 | 6 | 1165Rau0000004701 | 1263Mak0812941068 | 0 | EI2 60 | SA
SMT | 2.41 | 2.38799 | 1 | Stahl-Glas-Tür | N | - | E03-F01-001-1 | KD | BS | 1265Rau0000000034 | 1263Mak0812996394 | 9.24299 | 6 | 1165Rau0000004701 | 1263Mak0812996358 | 3.73623 | EI2 30 | SA
SMT | 2.41 | 2.063 | 25 | Technik-Tür |  |  | E03-F02-003-25 | KD | BS | 1265Rau0000000023 | 1263Mak0812945752 | 8.918 | 6 | 1165Rau0000004701 | 1263Mak0812941526 | 0 | EI2 30
SMT | 2.41 | 2.074 | 35 | Technik-Tür |  |  | E03-015-004-35 | KD | BGS | 1265Rau0000000023 | 1263Mak0812887457 | 8.529 | 7 | 1215Rau0000006896 | 1263Mak0812946535 | 0 | EI2 30
SMT | 2.9 | 1.574 | 36 | Technik-Tür | - | - | E03-F02-002-36 | DK | BS | 1265Rau0000000023 | 1263Mak0812906854 | 8.429 | 7 | 1215Rau0000006896 | 1263Mak0812947021 | 0 | EI2 30 | SA

# IfcDoor: SMT (3)
Type - PredefinedType: DOOR; OperationType: DOUBLE_DOOR_SINGLE_SWING; ParameterTakesPrecedence: no
Type - IfcDoorLiningProperties - LiningDepth: 0.08 m; LiningThickness: 0.08 m
OverallHeight: 2.95 m; OverallWidth: 2.56 m
AllplanAttributes (SMT) - Codetext: Codetext; Gewerk: Zimmer- und Holzbauarbeiten; V6: 0 m; V7: 0 m; V8: 0 m; V9: 0; Programmversion: 3.1; Text1: 163; Text4: Stahl-Glas-Tür; Funktion: Flurtür; Bezeichnung: SMT; Plugin_Bezeichnung: MainObject; Plugin_Objektname: SmartPartCompressed; Tragendes Bauteil: yes; Glasanteil_berücksichtigen: 100; Typ: 0; Version: 7.21; Brennbares Material: no; Brandverhalten: 0; Brandabschnittsdefinierendes Bauteil: no; Brandschutzklasse: A; ash T_Sichtschutz: -; ash R_Verweis Wandansicht: -; ash T_Zulage Schachttür: no; ash T_Dichtschließend: no; ash T_Panik: P; ash T_Zarge_Typ: BZ; ash T_Türschließer: -; ash T_Gewerk Los: -; ash T_Erforderl. Durchgangsbreite: 0 m; ash T_Türblatt sichtbar 2D: ja; ash T_Fluchtwegsicherung: -; ash T_Standflügel-Betätigung: -; ash T_Zusatzfunktion Türschließer: SR; ash T_Türschließer-Montage: -; ash T_Zusätzliche Rauchmelder: -; ash T_Zusätzl. Anschluss an BMA: -; ash T_Impulsgeber: S; ash T_Sicherheits-Sensorleisten: -; ash T_Anschl. an Zuttrittskontrolle: -; ash T_Anschl. an Einbruchmeld.anl.: -; ash T_Klemmschutz: -; ash T_LV-Positions-Nr.: -; ash T_Plan-Nr.: -; ash T_Sonstiges, Bemerkungen: -; ash T_Bodentürstopper: -; ash T_nicht abschließbar: no; ash T_Material Seitenteil: -; ash T_Strahlenschutz: 0.000000; ash T_Kantengeometrie: -; ash T_Kantenmaterial: -; ash T_Blatt_Oberfläche: L; ash T_Erford. Durgangshöhe: 0 m; ash T_Laserschutz: -; ash T_Rammschutz: SB; ash T_Fluchtwegrichtung: A; ash T_Anschlag Gangflügel: -; ash T_Bodendichtung: -; ash T_Lüftungsgitter: 0 m2; ash T_Feuchtebeständigkeit: -; ash T_E_Öffner: -; ash T_Automatik_Antrieb: M2; ash T_Blatt_Material: HO; ash T_Schlossfunktion: -; ash T_Schliesszylinder: PZ(v); ash T_Beschlag: StP; ash T_Glasausschnitt: -; ash T_Sonder_Wandmaterial: -; ash T_Anz_Reedkontakte: 0; ash T_Anz_Riegelkontakte: 0; ash T_Schallschutz: -; ash T_Zarge_Material: -; ash T_Bodeneinstand: -; ash T_Blatt_Farbe: -; ash T_Steuerung (BG): F; ash T_Steuerung (BS): B, F; Attributset-Objekt: Door; Abrechnungsart: St; Objektname: Türmakro, -SmartPart
AllplanQuantities - HeightWindowSillOutside: 0; HeightWindowSillInside: 0; OffsetOpeningTop: 0; OffsetOpeningLeft: 0; OffsetOpeningRight: 0; DeductionOpeningBottom: 200; DeductionOpeningLeft: 80; DeductionOpeningRight: 80; DeductionOpeningTop: 80
Pset_DoorCommon - Status: NEW; IsExternal: no; FireRating: EI2 60; ThermalTransmittance: 0 W/K/m2; AcousticRating: 0; SmokeStop: yes; SelfClosing: yes; Reference: Codetext
Name | In | Material = AllplanAttributes (SMT), Material | Ortscode_Geschoßbezeichnung | OKFF | ash T_Tür-Nr. | P_ID | Allright_Bauteil_ID | GlassSurface | OffsetOpeningBottom | HandicapAccessible = FireExit | Positionsnummer_Text
SMT | H2 Ebene +2 | TI-2F-AG-D-O | E02 | 7.5 | E02-T01a-001-163 | 1215Rau0000006911 | 1213Mak0813005464 | 5.07 | 150 | no
SMT | H2 Ebene +1 | TI-2F-SG-D | E01 | 3.75 | E01-F01-001-163 | 1165Rau0000004749 | 1163Mak0813652951 | 5.07 | 150 | no | U100 | AllplanAttributes (SMT) - ash T_Sturz: S; Pset_DoorCommon - SecurityRating: SA
SMT | H2 Ebene 0 | TI-2F-SG-D | E00 | 0 | E00-T01a-001-163 | 1115Rau0000005147 | 1113Mak0812934713 | 4.95 | 200 | yes | S68 | AllplanAttributes (SMT) - Text3: Handauslösetaster; ash T_Raum zugehörigkeit: BS

# IfcDoor: SMT (8)
Type - PredefinedType: DOOR; OperationType: DOUBLE_DOOR_SINGLE_SWING; ParameterTakesPrecedence: no
Type - IfcDoorLiningProperties - LiningDepth: 0.18 m; LiningThickness: 0.04 m
AllplanAttributes (SMT) - Gewerk: Metallbau-, Schlosserarbeiten; V6: 0 m; V7: 0 m; V8: 0 m; V9: 0; Objektname: Türmakro; Bezeichnung: SMT; Plugin_Bezeichnung: MainObject; Plugin_Objektname: SmartPartCompressed; Glasanteil_berücksichtigen: 100; ash T_Zulage Schachttür: no; ash T_Dichtschließend: no; ash T_Zarge_Typ: UZ; ash T_Erforderl. Durchgangsbreite: 0 m; ash T_Türblatt sichtbar 2D: ja; ash T_Feststellanlage (FSA): -; ash T_nicht abschließbar: no; ash T_Erford. Durgangshöhe: 0 m; ash T_Lüftungsgitter: 0 m2; ash T_Schliesszylinder: PZ; ash T_Anz_Reedkontakte: 0; ash T_Anz_Riegelkontakte: 0; ash T_Schallschutz: -; ash T_Zarge_Material: ST; Attributset-Objekt: Door; Abrechnungsart: St
AllplanAttributes (TGR 1.6) - V6: 0 m; V7: 0 m; V8: 0 m; V9: 0; Programmversion: 3.1; Objektname: TGR-Makro; Text1: PlanNo.; Bezeichnung: TGR 1.6; Plugin_Bezeichnung: MainObject; Plugin_Objektname: SmartPartCompressed; Version: 1.6; ash T_Türprofilnummer: 2; Abrechnungsart: St
AllplanQuantities - GlassSurface: 0; HeightWindowSillOutside: 0; HeightWindowSillInside: 0; OffsetOpeningTop: 0; OffsetOpeningLeft: 0; OffsetOpeningRight: 0; DeductionOpeningBottom: 100; DeductionOpeningLeft: 40; DeductionOpeningRight: 40; DeductionOpeningTop: 40
Pset_DoorCommon - Status: NEW; IsExternal: no; ThermalTransmittance: 0 W/K/m2; HandicapAccessible: no; FireExit: no
Name | In | OverallHeight (m) | OverallWidth (m) | Material = AllplanAttributes (SMT), Material | AllplanAttributes (SMT), Ortscode_Geschoßbezeichnung | Programmversion | Text1 | Version | ash T_Türschließer | AllplanAttributes (SMT), OKFF | ash T_Strahlenschutz | ash T_Tür-Nr. | ash T_Kantengeometrie | ash T_Blatt_Oberfläche | ash T_Anschlag Gangflügel | ash T_Blatt_Material | ash T_Beschlag | ash T_Raum zugehörigkeit | P_ID | AllplanAttributes (SMT), Allright_Bauteil_ID | AllplanAttributes (TGR 1.6), Codetext | Gesamtlänge | AllplanAttributes (TGR 1.6), OKFF | AllplanAttributes (TGR 1.6), Allright_Bauteil_ID | OffsetOpeningBottom | SmokeStop = SelfClosing | ash T_Sichtschutz = ash R_Verweis Wandansicht = ash T_Panik = ash T_Gewerk Los = ash T_Zusatzfunktion Panikschloss = ash T_Fluchtwegsicherung = ash T_Standflügel-Betätigung = ash T_Zusatzfunktion Türschließer = ash T_Türschließer-Montage = ash T_Zusätzliche Rauchmelder = ash T_Zusätzl. Anschluss an BMA = ash T_Impulsgeber = ash T_Sicherheits-Sensorleisten = ash T_Anschl. an Einbruchmeld.anl. = ash T_Klemmschutz = ash T_LV-Positions-Nr. = ash T_Plan-Nr. = ash T_Sonstiges, Bemerkungen = ash T_Bodentürstopper = ash T_Material Seitenteil = ash T_Fluchtwegrichtung = ash T_Bodendichtung = ash T_Feuchtebeständigkeit = ash T_E_Öffner = ash T_Automatik_Antrieb = ash T_Sturz = ash T_Schlossfunktion = ash T_Glasausschnitt = ash T_Sonder_Wandmaterial = ash T_Bodeneinstand = ash T_Blatt_Farbe | ash T_Kantenmaterial | ash T_Rammschutz
SMT | H2 Ebene +3 | 2.41 | 2.01 | TI-2F-AG-D-UZ | E03 | 3.0 | 12 | 8.11 | OTS | 11.25 | 0.000000 | E03-006-001-12 | LF | L | - | ST | DK | BS | 1266Rau0000012749 | 1263Mak0812976168 | Typ | 8.86 | 11.25 | 1263Mak0812976166 | 150 | yes | AllplanAttributes (SMT) - Codetext: Codetext; Text2: -; Text4: Technik-Tür; Tragendes Bauteil: yes; Typ: 0; Brennbares Material: no; Brandverhalten: 0; Brandabschnittsdefinierendes Bauteil: no; Brandschutzklasse: A; Pset_DoorCommon - FireRating: EI2 30; AcousticRating: 0; Reference: Codetext
SMT | H2 Ebene +3 | 2.41 | 2.01 | TI-2F-AG-D-UZ | E03 | 3.0 | 38 | 8.11 | OTS | 11.25 | 0.000000 | E03-018-001-38 | LF | L | - | ST | DK | BS | 1266Rau0000012761 | 1263Mak0812735049 | Typ | 8.86 | 11.25 | 1263Mak0812947444 | 150 | yes | AllplanAttributes (SMT) - Codetext: Codetext; Text2: -; Text4: Technik-Tür; Tragendes Bauteil: yes; Typ: 0; Brennbares Material: no; Brandverhalten: 0; Brandabschnittsdefinierendes Bauteil: no; Brandschutzklasse: A; Pset_DoorCommon - FireRating: EI2 30; AcousticRating: 0; Reference: Codetext
SMT | H2 Ebene +2 | 2.41 | 1.26 | TI-2F-UZ-D | E02 | 3.1 | 37 | 7.21 | - | 7.5 |  | E02-026-001-37 | 2F | HPL |  | HO | KD | BGS | 1215Rau0000006926 | 1213Mak0813004772 | Typ | 8.36 | 7.5 | 1213Mak0813223752 | 150 | no | - | PU | BL | AllplanAttributes (TGR 1.6) - Ortscode_Geschoßbezeichnung: E02
SMT | H2 Ebene +2 | 2.41 | 1.26 | TI-1F-UZ-D | E02 | 3.1 | 137 | 7.21 | - | 7.5 |  | E02-089-001-137 | 2F | HPL |  | HO | KD | BGS | 1215Rau0000006893 | 1213Mak0813004778 | Typ | 8.36 | 7.5 | 1213Mak0813223937 | 150 | no | - | PU | BL | AllplanAttributes (TGR 1.6) - Ortscode_Geschoßbezeichnung: E02
SMT | H2 Ebene +1 | 2.41 | 1.26 | TI-2F-UZ-D | E01 | 3.1 | 37 | 7.21 | - | 3.75 | 0.000000 | E01-026-001-37 | 2F | HPL | - | HO | KD | BGS | 1165Rau0000004651 | 1163Mak0812549304 | Typ | 8.36 |  | 1163Mak0814151011 | 150 | no | - | PU | BL | AllplanAttributes (SMT) - Positionsnummer_Text: U100; AllplanAttributes (TGR 1.6) - Positionsnummer_Text: U100
SMT | H2 Ebene +1 | 2.41 | 1.26 | TI-2F-UZ-D | E01 | 3.1 | 137 | 7.21 | - | 3.75 | 0.000000 | E01-089-001-137 | 2F | HPL | - | HO | KD | BGS | 1165Rau0000004736 | 1163Mak0812436826 | Typ | 8.36 |  | 1163Mak0814151231 | 150 | no | - | PU | BL | AllplanAttributes (SMT) - Positionsnummer_Text: U100; AllplanAttributes (TGR 1.6) - Positionsnummer_Text: U100
SMT | H2 Ebene 0 | 2.46 | 1.26 | TI-2F-UZ-D | E00 | 3.1 | 37 | 7.21 | - | 0 | 0.000000 | E00-026-001-37 | 2F | HPL | - | HO | KD | BGS | 1115Rau0000005119 | 1113Mak0812549304 |  | 8.46 | 0 | 1113Mak0813547689 | 200 | no | - | PU | BL | AllplanAttributes (SMT) - Positionsnummer_Text: S68; AllplanAttributes (TGR 1.6) - Positionsnummer_Text: S68
SMT | H2 Ebene 0 | 2.46 | 1.26 | TI-1F-UZ-D | E00 | 3.1 | 137 | 7.21 | - | 0 | 0.000000 | E00-089-001-137 | 2F | HPL | - | HO | KD | BGS | 1115Rau0000005201 | 1113Mak0812436826 | Typ | 8.46 | 0 | 1113Mak0813548028 | 200 | no | - | PU | BL | AllplanAttributes (SMT) - Positionsnummer_Text: S68; AllplanAttributes (TGR 1.6) - Positionsnummer_Text: S68

# IfcDoor: SMT (47)
Type - PredefinedType: DOOR; OperationType: DOUBLE_DOOR_SINGLE_SWING; ParameterTakesPrecedence: no
Type - IfcDoorLiningProperties - LiningDepth: 0.262 m; LiningThickness: 0.04 m
OverallWidth: 1.26 m; Material: TI-2F-UZ-D
AllplanAttributes (SMT) - Gewerk: Zimmer- und Holzbauarbeiten; V6: 0 m; V7: 0 m; V8: 0 m; V9: 0; Programmversion: 3.1; Objektname: Türmakro; Bezeichnung: SMT; Material: TI-2F-UZ-D; Plugin_Bezeichnung: MainObject; Plugin_Objektname: SmartPartCompressed; Glasanteil_berücksichtigen: 100; Version: 7.21; ash T_Sichtschutz: -; ash R_Verweis Wandansicht: -; ash T_Zulage Schachttür: no; ash T_Dichtschließend: yes; ash T_Panik: -; ash T_Zarge_Typ: UZ; ash T_Türschließer: -; ash T_Gewerk Los: -; ash T_Erforderl. Durchgangsbreite: 0 m; ash T_Türblatt sichtbar 2D: ja; ash T_Zusatzfunktion Panikschloss: -; ash T_Fluchtwegsicherung: -; ash T_Standflügel-Betätigung: -; ash T_Zusatzfunktion Türschließer: -; ash T_Türschließer-Montage: -; ash T_Feststellanlage (FSA): -; ash T_Zusätzliche Rauchmelder: -; ash T_Zusätzl. Anschluss an BMA: -; ash T_Impulsgeber: -; ash T_Sicherheits-Sensorleisten: -; ash T_Anschl. an Einbruchmeld.anl.: -; ash T_Klemmschutz: -; ash T_LV-Positions-Nr.: -; ash T_Plan-Nr.: -; ash T_Sonstiges, Bemerkungen: -; ash T_Bodentürstopper: -; ash T_nicht abschließbar: no; ash T_Material Seitenteil: -; ash T_Strahlenschutz: 0.000000; ash T_Kantengeometrie: 2F; ash T_Kantenmaterial: PU; ash T_Blatt_Oberfläche: HPL; ash T_Erford. Durgangshöhe: 0 m; ash T_Rammschutz: BL; ash T_Fluchtwegrichtung: -; ash T_Anschlag Gangflügel: -; ash T_Bodendichtung: Ja; ash T_Lüftungsgitter: 0 m2; ash T_Feuchtebeständigkeit: -; ash T_E_Öffner: -; ash T_Automatik_Antrieb: -; ash T_Sturz: -; ash T_Blatt_Material: HO; ash T_Schlossfunktion: -; ash T_Schliesszylinder: ePZ; ash T_Beschlag: DD; ash T_Glasausschnitt: -; ash T_Sonder_Wandmaterial: -; ash T_Anz_Reedkontakte: 0; ash T_Anz_Riegelkontakte: 0; ash T_Zarge_Material: ST; ash T_Bodeneinstand: -; ash T_Raum zugehörigkeit: BGS; ash T_Blatt_Farbe: -; Attributset-Objekt: Door; Abrechnungsart: St
AllplanQuantities - GlassSurface: 0; HeightWindowSillOutside: 0; HeightWindowSillInside: 0; OffsetOpeningTop: 0; OffsetOpeningLeft: 0; OffsetOpeningRight: 0; DeductionOpeningBottom: 100; DeductionOpeningLeft: 40; DeductionOpeningRight: 40; DeductionOpeningTop: 40
Pset_DoorCommon - Status: NEW; IsExternal: no; FireRating: -; ThermalTransmittance: 0 W/K/m2; SmokeStop: no; SelfClosing: no; FireExit: no
Name | In | OverallHeight (m) | Ortscode_Geschoßbezeichnung | Text1 | OKFF | ash T_Tür-Nr. | ash T_Schallschutz | Positionsnummer_Text | P_ID | Allright_Bauteil_ID | OffsetOpeningBottom | HandicapAccessible
SMT | H2 Ebene +1 | 2.41 | E01 | 58 | 3.75 | E01-042-001-58 | 32 dB | U100 | 1165Rau0000004688 | 1163Mak0814518763 | 150 | no
SMT | H2 Ebene +1 | 2.41 | E01 | 62 | 3.75 | E01-044-001-62 | 32 dB | U100 | 1165Rau0000004688 | 1163Mak0814519938 | 150 | no
SMT | H2 Ebene +1 | 2.41 | E01 | 63 | 3.75 | E01-045-001-63 | 32 dB | U100 | 1165Rau0000004688 | 1163Mak0814519913 | 150 | no
SMT | H2 Ebene +1 | 2.41 | E01 | 67 | 3.75 | E01-047-001-67 | 32 dB | U100 | 1165Rau0000004688 | 1163Mak0814520605 | 150 | no
SMT | H2 Ebene +1 | 2.41 | E01 | 66 | 3.75 | E01-046-001-66 | 32 dB | U100 | 1165Rau0000004688 | 1163Mak0814520600 | 150 | no
SMT | H2 Ebene +1 | 2.41 | E01 | 35 | 3.75 | E01-025-001-35 | 32 dB | U100 | 1165Rau0000004651 | 1163Mak0812446115 | 150 | no
SMT | H2 Ebene +1 | 2.41 | E01 | 31 | 3.75 | E01-023-001-31 | 32 dB | U100 | 1165Rau0000004651 | 1163Mak0814581588 | 150 | no
SMT | H2 Ebene +1 | 2.41 | E01 | 34 | 3.75 | E01-024-001-34 | 32 dB | U100 | 1165Rau0000004651 | 1163Mak0814581600 | 150 | no
SMT | H2 Ebene +1 | 2.41 | E01 | 30 | 3.75 | E01-022a-001-30 | 32 dB | U100 | 1165Rau0000004651 | 1163Mak0814582761 | 150 | no
SMT | H2 Ebene +1 | 2.41 | E01 | 27 | 3.75 | E01-021-001-27 | 32 dB | U100 | 1165Rau0000004651 | 1163Mak0814582741 | 150 | no
SMT | H2 Ebene +1 | 2.41 | E01 | 26 | 3.75 | E01-020-001-26 | 32 dB | U100 | 1165Rau0000004651 | 1163Mak0814583432 | 150 | no
SMT | H2 Ebene +1 | 2.41 | E01 | 23 | 3.75 | E01-019-001-23 | 32 dB | U100 | 1165Rau0000004651 | 1163Mak0814583422 | 150 | no
SMT | H2 Ebene +1 | 2.41 | E01 | 150 | 3.75 | E01-095-001-150 | 32 dB | U100 | 1165Rau0000004736 | 1163Mak0812438214 | 150 | no
SMT | H2 Ebene +1 | 2.41 | E01 | 151 | 3.75 | E01-096-001-151 | 32 dB | U100 | 1165Rau0000004736 | 1163Mak0812438218 | 150 | no
SMT | H2 Ebene +1 | 2.41 | E01 | 147 | 3.75 | E01-025a-001-147 | 32 dB | U100 | 1165Rau0000004736 | 1163Mak0814659981 | 150 | no
SMT | H2 Ebene +1 | 2.41 | E01 | 146 | 3.75 | E01-093a-001-146 | 32 dB | U100 | 1165Rau0000004736 | 1163Mak0814659971 | 150 | no
SMT | H2 Ebene +1 | 2.41 | E01 | 142 | 3.75 | E01-091-001-142 | 32 dB | U100 | 1165Rau0000004736 | 1163Mak0814660797 | 150 | no
SMT | H2 Ebene +1 | 2.41 | E01 | 143 | 3.75 | E01-092-001-143 | 32 dB | U100 | 1165Rau0000004736 | 1163Mak0814660777 | 150 | no
SMT | H2 Ebene +1 | 2.41 | E01 | 139 | 3.75 | E01-090-001-139 | 32 dB | U100 | 1165Rau0000004736 | 1163Mak0814661293 | 150 | no
SMT | H2 Ebene +1 | 2.41 | E01 | 119 | 3.75 | E01-074-001-119 | 32 dB | U100 | 1165Rau0000004712 | 1163Mak0814677001 | 150 | no
SMT | H2 Ebene +1 | 2.41 | E01 | 115 | 3.75 | E01-072-001-115 | 32 dB | U100 | 1165Rau0000004712 | 1163Mak0814678294 | 150 | no
SMT | H2 Ebene +1 | 2.41 | E01 | 116 | 3.75 | E01-073-001-116 | 32 dB | U100 | 1165Rau0000004712 | 1163Mak0814678279 | 150 | no
SMT | H2 Ebene +1 | 2.41 | E01 | 107 | 3.75 | E01-068-001-107 | 32 dB | U100 | 1165Rau0000004712 | 1163Mak0812439021 | 150 | no
SMT | H2 Ebene +1 | 2.41 | E01 | 108 | 3.75 | E01-069-001-108 | 32 dB | U100 | 1165Rau0000004712 | 1163Mak0812439029 | 150 | no
SMT | H2 Ebene +1 | 2.41 | E01 | 111 | 3.75 | E01-070-001-111 | 32 dB | U100 | 1165Rau0000004712 | 1163Mak0814679120 | 150 | no
SMT | H2 Ebene +1 | 2.41 | E01 | 112 | 3.75 | E01-071-001-112 | 32 dB | U100 | 1165Rau0000004712 | 1163Mak0814679115 | 150 | no
SMT | H2 Ebene +1 | 2.41 | E01 | 55 | 3.75 | E01-041-001-55 | 32 dB | U100 | 1165Rau0000004688 | 1163Mak0812440682 | 150 | no
SMT | H2 Ebene 0 | 2.46 | E00 | 55 | 0 | E00-041-001-55 | 32 dB | S68 | 1115Rau0000005169 | 1113Mak0814115563 | 200 | no
SMT | H2 Ebene 0 | 2.46 | E00 | 62 | 0 | E00-044-000-62 | 32 dB | S68 | 1115Rau0000005169 | 1113Mak0814121346 | 200 | no
SMT | H2 Ebene 0 | 2.46 | E00 | 63 | 0 | E00-045-001-63 | 32 dB | S68 | 1115Rau0000005169 | 1113Mak0814121367 | 200 | no
SMT | H2 Ebene 0 | 2.46 | E00 | 31 | 0 | E00-023-001-31 | 32 dB | S68 | 1115Rau0000005119 | 1113Mak0814125152 | 200 | yes
SMT | H2 Ebene 0 | 2.46 | E00 | 34 | 0 | E00-024-001-34 | 32 dB | S68 | 1115Rau0000005119 | 1113Mak0814125178 | 200 | no
SMT | H2 Ebene 0 | 2.46 | E00 | 30 | 0 | E00-022-001-30 | 32 dB | S68 | 1115Rau0000005119 | 1113Mak0814128471 | 200 | no
SMT | H2 Ebene 0 | 2.46 | E00 | 27 | 0 | E00-021-001-27 | 32 dB | S68 | 1115Rau0000005119 | 1113Mak0814128484 | 200 | no
SMT | H2 Ebene 0 | 2.46 | E00 | 108 | 0 | E00-069-001-108 | 32 | S68 | 1115Rau0000005223 | 1113Mak0814141538 | 200 | no
SMT | H2 Ebene 0 | 2.46 | E00 | 111 | 0 | E00-070-001-111 | 32 dB | S68 | 1115Rau0000005223 | 1113Mak0814142093 | 200 | no
SMT | H2 Ebene 0 | 2.46 | E00 | 112 | 0 | E00-071-001-112 | 32 dB | S68 | 1115Rau0000005223 | 1113Mak0814142077 | 200 | no
SMT | H2 Ebene 0 | 2.46 | E00 | 116 | 0 | E00-073-001-116 | 32 dB | S68 | 1115Rau0000005223 | 1113Mak0814143154 | 200 | no
SMT | H2 Ebene 0 | 2.46 | E00 | 115 | 0 | E00-072-001-115 | 32 dB | S68 | 1115Rau0000005223 | 1113Mak0814143151 | 200 | yes
SMT | H2 Ebene 0 | 2.46 | E00 | 119 | 0 | E00-074-001-119 | 32 dB | S68 | 1115Rau0000005223 | 1113Mak0812439045 | 200 | no
SMT | H2 Ebene 0 | 2.46 | E00 | 58 | 0 | E00-042-001-58 | 32 dB | S68 | 1115Rau0000005169 | 1113Mak0814180092 | 200 | no
SMT | H2 Ebene 0 | 2.46 | E00 | 67 | 0 | E00-047-001-67 | 32 dB | S68 | 1115Rau0000005169 | 1113Mak0812440697 | 200 | no
SMT | H2 Ebene 0 | 2.46 | E00 | 66 | 0 | E00-046-001-66 | 32 dB | S68 | 1115Rau0000005169 | 1113Mak0812440694 | 200 | no
SMT | H2 Ebene 0 | 2.46 | E00 | 107 | 0 | E00-068-001-107 | 32 dB | S68 | 1115Rau0000005223 | 1113Mak0814139862 | 200 | no
SMT | H2 Ebene 0 | 2.46 | E00 | 23 | 0 | E00-019-001-23 | 32 dB | S68 | 1115Rau0000005119 | 1113Mak0814130099 | 200 | no
SMT | H2 Ebene 0 | 2.46 | E00 | 26 | 0 | E00-020-001-26 | 32 dB | S68 | 1115Rau0000005119 | 1113Mak0814130105 | 200 | no
SMT | H2 Ebene 0 | 2.46 | E00 | 139 | 0 | E00-090-001-139 | 32 dB | S68 | 1115Rau0000005201 | 1113Mak0814187188 | 200 | no

# IfcDoor: SMT (7)
In: H2 Ebene 0
Type - PredefinedType: DOOR; OperationType: DOUBLE_DOOR_SINGLE_SWING; ParameterTakesPrecedence: no
Type - IfcDoorLiningProperties - LiningDepth: 0.301 m; LiningThickness: 0.04 m
OverallHeight: 2.46 m; OverallWidth: 1.26 m; Material: TI-2F-UZ-D
AllplanAttributes (SMT) - Gewerk: Zimmer- und Holzbauarbeiten; V6: 0 m; V7: 0 m; V8: 0 m; V9: 0; Ortscode_Geschoßbezeichnung: E00; Programmversion: 3.1; Objektname: Türmakro; Bezeichnung: SMT; Material: TI-2F-UZ-D; Plugin_Bezeichnung: MainObject; Plugin_Objektname: SmartPartCompressed; Glasanteil_berücksichtigen: 100; Version: 7.21; ash T_Sichtschutz: -; ash R_Verweis Wandansicht: -; ash T_Zulage Schachttür: no; ash T_Dichtschließend: yes; ash T_Panik: -; ash T_Zarge_Typ: UZ; ash T_Türschließer: -; ash T_Gewerk Los: -; ash T_Erforderl. Durchgangsbreite: 0 m; ash T_Türblatt sichtbar 2D: ja; ash T_Zusatzfunktion Panikschloss: -; ash T_Fluchtwegsicherung: -; ash T_Standflügel-Betätigung: -; ash T_Zusatzfunktion Türschließer: -; ash T_Türschließer-Montage: -; ash T_Feststellanlage (FSA): -; ash T_Zusätzliche Rauchmelder: -; ash T_Zusätzl. Anschluss an BMA: -; ash T_Impulsgeber: -; ash T_Sicherheits-Sensorleisten: -; ash T_Anschl. an Einbruchmeld.anl.: -; ash T_Klemmschutz: -; ash T_LV-Positions-Nr.: -; ash T_Plan-Nr.: -; ash T_Sonstiges, Bemerkungen: -; OKFF: 0; ash T_Bodentürstopper: -; ash T_nicht abschließbar: no; ash T_Material Seitenteil: -; ash T_Strahlenschutz: 0.000000; ash T_Kantengeometrie: 2F; ash T_Kantenmaterial: PU; ash T_Blatt_Oberfläche: HPL; ash T_Erford. Durgangshöhe: 0 m; ash T_Rammschutz: BL; ash T_Fluchtwegrichtung: -; ash T_Anschlag Gangflügel: -; ash T_Bodendichtung: Ja; ash T_Lüftungsgitter: 0 m2; ash T_Feuchtebeständigkeit: -; ash T_E_Öffner: -; ash T_Automatik_Antrieb: -; ash T_Sturz: -; ash T_Blatt_Material: HO; ash T_Schlossfunktion: -; ash T_Schliesszylinder: ePZ; ash T_Beschlag: DD; ash T_Glasausschnitt: -; ash T_Sonder_Wandmaterial: -; ash T_Anz_Reedkontakte: 0; ash T_Anz_Riegelkontakte: 0; ash T_Schallschutz: 32 dB; ash T_Zarge_Material: ST; ash T_Bodeneinstand: -; ash T_Raum zugehörigkeit: BGS; ash T_Blatt_Farbe: -; Positionsnummer_Text: S68; Attributset-Objekt: Door; Abrechnungsart: St
AllplanQuantities - GlassSurface: 0; HeightWindowSillOutside: 0; HeightWindowSillInside: 0; OffsetOpeningBottom: 200; OffsetOpeningTop: 0; OffsetOpeningLeft: 0; OffsetOpeningRight: 0; DeductionOpeningBottom: 100; DeductionOpeningLeft: 40; DeductionOpeningRight: 40; DeductionOpeningTop: 40
Pset_DoorCommon - Status: NEW; IsExternal: no; FireRating: -; ThermalTransmittance: 0 W/K/m2; SmokeStop: no; SelfClosing: no; FireExit: no
Name | Text1 | ash T_Tür-Nr. | P_ID | Allright_Bauteil_ID | HandicapAccessible
SMT | 35 | E00-025-001-35 | 1115Rau0000005119 | 1113Mak0812446115 | no
SMT | 147 | E00-094-001-147 | 1115Rau0000005201 | 1113Mak0814133507 | no
SMT | 146 | E00-093-001-146 | 1115Rau0000005201 | 1113Mak0814133519 | no
SMT | 150 | E00-095-001-150 | 1115Rau0000005201 | 1113Mak0812438214 | no
SMT | 151 | E00-096-001-151 | 1115Rau0000005201 | 1113Mak0812438218 | no
SMT | 143 | E00-092-001-143 | 1115Rau0000005201 | 1113Mak0814138065 | yes
SMT | 142 | E00-091-001-142 | 1115Rau0000005201 | 1113Mak0814138071 | no

# IfcDoor: SMT (34)
Type - PredefinedType: DOOR; OperationType: DOUBLE_DOOR_SINGLE_SWING; ParameterTakesPrecedence: no
Type - IfcDoorLiningProperties - LiningDepth: 0.302 m; LiningThickness: 0.04 m
OverallWidth: 1.26 m; Material: TI-2F-UZ-D
AllplanAttributes (SMT) - Gewerk: Zimmer- und Holzbauarbeiten; V6: 0 m; V7: 0 m; V8: 0 m; V9: 0; Programmversion: 3.1; Objektname: Türmakro; Bezeichnung: SMT; Material: TI-2F-UZ-D; Plugin_Bezeichnung: MainObject; Plugin_Objektname: SmartPartCompressed; Glasanteil_berücksichtigen: 100; Version: 7.21; ash T_Sichtschutz: -; ash R_Verweis Wandansicht: -; ash T_Zulage Schachttür: no; ash T_Dichtschließend: yes; ash T_Panik: -; ash T_Zarge_Typ: UZ; ash T_Türschließer: -; ash T_Gewerk Los: -; ash T_Erforderl. Durchgangsbreite: 0 m; ash T_Türblatt sichtbar 2D: ja; ash T_Zusatzfunktion Panikschloss: -; ash T_Fluchtwegsicherung: -; ash T_Standflügel-Betätigung: -; ash T_Zusatzfunktion Türschließer: -; ash T_Türschließer-Montage: -; ash T_Feststellanlage (FSA): -; ash T_Zusätzliche Rauchmelder: -; ash T_Zusätzl. Anschluss an BMA: -; ash T_Impulsgeber: -; ash T_Sicherheits-Sensorleisten: -; ash T_Anschl. an Einbruchmeld.anl.: -; ash T_Klemmschutz: -; ash T_LV-Positions-Nr.: -; ash T_Plan-Nr.: -; ash T_Sonstiges, Bemerkungen: -; ash T_Bodentürstopper: -; ash T_nicht abschließbar: no; ash T_Material Seitenteil: -; ash T_Kantengeometrie: 2F; ash T_Kantenmaterial: PU; ash T_Blatt_Oberfläche: HPL; ash T_Erford. Durgangshöhe: 0 m; ash T_Rammschutz: BL; ash T_Fluchtwegrichtung: -; ash T_Bodendichtung: Ja; ash T_Lüftungsgitter: 0 m2; ash T_Feuchtebeständigkeit: -; ash T_E_Öffner: -; ash T_Automatik_Antrieb: -; ash T_Sturz: -; ash T_Blatt_Material: HO; ash T_Schlossfunktion: -; ash T_Schliesszylinder: ePZ; ash T_Beschlag: DD; ash T_Glasausschnitt: -; ash T_Sonder_Wandmaterial: -; ash T_Anz_Reedkontakte: 0; ash T_Anz_Riegelkontakte: 0; ash T_Schallschutz: 32 dB; ash T_Zarge_Material: ST; ash T_Bodeneinstand: -; ash T_Raum zugehörigkeit: BGS; ash T_Blatt_Farbe: -; Attributset-Objekt: Door; Abrechnungsart: St
AllplanQuantities - GlassSurface: 0; HeightWindowSillOutside: 0; HeightWindowSillInside: 0; OffsetOpeningTop: 0; OffsetOpeningLeft: 0; OffsetOpeningRight: 0; DeductionOpeningBottom: 100; DeductionOpeningLeft: 40; DeductionOpeningRight: 40; DeductionOpeningTop: 40
Pset_DoorCommon - Status: NEW; IsExternal: no; FireRating: -; ThermalTransmittance: 0 W/K/m2; SmokeStop: no; SelfClosing: no; FireExit: no
Name | In | OverallHeight (m) | Ortscode_Geschoßbezeichnung | Text1 | OKFF | ash T_Tür-Nr. | P_ID | Allright_Bauteil_ID | OffsetOpeningBottom | HandicapAccessible
SMT | H2 Ebene +2 | 2.41 | E02 | 55 | 7.5 | E02-041-001-55 | 1215Rau0000006899 | 1213Mak0813004578 | 150 | no
SMT | H2 Ebene +2 | 2.41 | E02 | 58 | 7.5 | E02-042-001-58 | 1215Rau0000006899 | 1213Mak0813580094 | 150 | no
SMT | H2 Ebene +2 | 2.41 | E02 | 59 | 7.5 | E02-043-001-59 | 1215Rau0000006899 | 1213Mak0813580106 | 150 | no | AllplanAttributes (SMT) - ash T_Anschl. an Zuttrittskontrolle: -; ash T_Strahlenschutz: 0.000000; ash T_Laserschutz: -; ash T_Anschlag Gangflügel: -; ash D_Detailverweis: D2; ash D_Plannummer: 1684; Pset_DoorCommon - SecurityRating: SA
SMT | H2 Ebene +2 | 2.41 | E02 | 62 | 7.5 | E02-044-000-62 | 1215Rau0000006899 | 1213Mak0813580868 | 150 | no
SMT | H2 Ebene +2 | 2.41 | E02 | 63 | 7.5 | E02-045-001-63 | 1215Rau0000006899 | 1213Mak0813580877 | 150 | no
SMT | H2 Ebene +2 | 2.41 | E02 | 66 | 7.5 | E02-046-001-66 | 1215Rau0000006899 | 1213Mak0813581416 | 150 | no
SMT | H2 Ebene +2 | 2.41 | E02 | 67 | 7.5 | E02-047-001-67 | 1215Rau0000006899 | 1213Mak0813581422 | 150 | no
SMT | H2 Ebene +2 | 2.41 | E02 | 35 | 7.5 | E02-025-001-35 | 1215Rau0000006926 | 1213Mak0813004614 | 150 | no
SMT | H2 Ebene +2 | 2.41 | E02 | 31 | 7.5 | E02-023-001-31 | 1215Rau0000006926 | 1213Mak0813592957 | 150 | no
SMT | H2 Ebene +2 | 2.41 | E02 | 34 | 7.5 | E02-024-001-34 | 1215Rau0000006926 | 1213Mak0813592960 | 150 | no
SMT | H2 Ebene +2 | 2.41 | E02 | 27 | 7.5 | E02-021-001-27 | 1215Rau0000006926 | 1213Mak0813593917 | 150 | no
SMT | H2 Ebene +2 | 2.41 | E02 | 30 | 7.5 | E02-022-001-30 | 1215Rau0000006926 | 1213Mak0813593921 | 150 | no
SMT | H2 Ebene +2 | 2.41 | E02 | 26 | 7.5 | E02-020-001-26 | 1215Rau0000006926 | 1213Mak0813594498 | 150 | no
SMT | H2 Ebene +2 | 2.41 | E02 | 23 | 7.5 | E02-019-001-23 | 1215Rau0000006926 | 1213Mak0813594494 | 150 | no
2 x SMT | H2 Ebene +2 | 2.46 | E02 | 150 | 7.5 | E02-095-001-150 | 1215Rau0000006893 | 1213Mak0813004281 | 150 | no
2 x SMT | H2 Ebene +2 | 2.46 | E02 | 151 | 7.5 | E02-096-001-151 | 1215Rau0000006893 | 1213Mak0813004287 | 150 | no
SMT | H2 Ebene +2 | 2.41 | E02 | 146 | 7.5 | E02-093-001-146 | 1215Rau0000006893 | 1213Mak0813622269 | 150 | no
SMT | H2 Ebene +2 | 2.41 | E02 | 147 | 7.5 | E02-094-001-147 | 1215Rau0000006893 | 1213Mak0813622272 | 150 | no
SMT | H2 Ebene +2 | 2.41 | E02 | 143 | 7.5 | E02-092-001-143 | 1215Rau0000006893 | 1213Mak0813623056 | 150 | no
SMT | H2 Ebene +2 | 2.41 | E02 | 142 | 7.5 | E02-091-001-142 | 1215Rau0000006893 | 1213Mak0813623060 | 150 | no
SMT | H2 Ebene +2 | 2.41 | E02 | 139 | 7.5 | E02-090-001-139 | 1215Rau0000006893 | 1213Mak0813623479 | 150 | no | AllplanAttributes (SMT) - ash T_Strahlenschutz: 0.000000; ash T_Anschlag Gangflügel: -
SMT | H2 Ebene +2 | 2.41 | E02 | 119 | 7.5 | E02-074-001-119 | 1215Rau0000006914 | 1213Mak0813635075 | 150 | no
SMT | H2 Ebene +2 | 2.41 | E02 | 115 | 7.5 | E02-072-001-115 | 1215Rau0000006914 | 1213Mak0813636003 | 150 | no
SMT | H2 Ebene +2 | 2.41 | E02 | 116 | 7.5 | E02-073-001-116 | 1215Rau0000006914 | 1213Mak0813636007 | 150 | no
2 x SMT | H2 Ebene +2 | 2.46 | E02 | 108 | 7.5 | E02-069-001-108 | 1215Rau0000006914 | 1213Mak0813004425 | 150 | no
2 x SMT | H2 Ebene +2 | 2.46 | E02 | 107 | 7.5 | E02-068-001-107 | 1215Rau0000006914 | 1213Mak0813004395 | 150 | no
SMT | H2 Ebene +2 | 2.41 | E02 | 111 | 7.5 | E02-070-001-111 | 1215Rau0000006914 | 1213Mak0813636631 | 150 | no
SMT | H2 Ebene +2 | 2.41 | E02 | 112 | 7.5 | E02-071-001-112 | 1215Rau0000006914 | 1213Mak0813636639 | 150 | no
SMT | H2 Ebene +1 | 2.41 | E01 | 59 | 3.75 | E01-043-001-59 | 1165Rau0000004688 | 1163Mak0814518774 | 150 | no | AllplanAttributes (SMT) - ash T_Anschl. an Zuttrittskontrolle: -; ash T_Strahlenschutz: 0.000000; ash T_Laserschutz: -; ash T_Anschlag Gangflügel: -; ash D_Detailverweis: D2; ash D_Plannummer: 1684; Positionsnummer_Text: U100; Pset_DoorCommon - SecurityRating: SA
SMT | H2 Ebene 0 | 2.46 | E00 | 59 | 0 | E00-043-001-59 | 1115Rau0000005169 | 1113Mak0814119102 | 200 | yes | AllplanAttributes (SMT) - ash T_Anschl. an Zuttrittskontrolle: -; ash T_Strahlenschutz: 0.000000; ash T_Laserschutz: -; ash T_Anschlag Gangflügel: -; ash D_Detailverweis: D2; ash D_Plannummer: 1684; Positionsnummer_Text: S68; Pset_DoorCommon - SecurityRating: SA

# IfcDoor: SMT
In: H2 Ebene +1
Type - PredefinedType: DOOR; OperationType: SINGLE_SWING_LEFT; ParameterTakesPrecedence: no
OverallHeight: 2.5 m; OverallWidth: 1.5 m; Material: TI-1F-AG-DK
AllplanAttributes (SMT) - Gewerk: Metallbau-, Schlosserarbeiten; V6: 0 m; V7: 0 m; V8: 0 m; V9: 0; Ortscode_Geschoßbezeichnung: E01; Programmversion: 3.1; Text1: 40a; Bezeichnung: SMT; Material: TI-1F-AG-DK; Plugin_Bezeichnung: MainObject; Plugin_Objektname: SmartPartCompressed; Glasanteil_berücksichtigen: 100; Version: 7.21; ash T_Sichtschutz: -; ash T_Zulage Schachttür: no; ash T_Dichtschließend: no; ash T_Panik: -; ash T_Zarge_Typ: -; ash T_Türschließer: OTS; ash T_Gewerk Los: -; ash T_Erforderl. Durchgangsbreite: 0 m; ash T_Türblatt sichtbar 2D: ja; ash T_Zusatzfunktion Panikschloss: -; ash T_Fluchtwegsicherung: -; ash T_Standflügel-Betätigung: -; ash T_Zusatzfunktion Türschließer: -; ash T_Türschließer-Montage: -; ash T_Feststellanlage (FSA): -; ash T_Zusätzliche Rauchmelder: -; ash T_Zusätzl. Anschluss an BMA: -; ash T_Impulsgeber: -; ash T_Sicherheits-Sensorleisten: -; ash T_Anschl. an Zuttrittskontrolle: ZK; ash T_Anschl. an Einbruchmeld.anl.: -; ash T_Klemmschutz: -; ash T_LV-Positions-Nr.: -; ash T_Plan-Nr.: -; ash T_Sonstiges, Bemerkungen: -; OKFF: 5.11; ash T_Bodentürstopper: -; ash T_nicht abschließbar: no; ash T_Material Seitenteil: -; ash T_Strahlenschutz: -; ash T_Tür-Nr.: E01-T02-002-40a; ash T_Kantengeometrie: -; ash T_Kantenmaterial: -; ash T_Blatt_Oberfläche: -; ash T_Erford. Durgangshöhe: 0 m; ash T_Laserschutz: -; ash T_Rammschutz: -; ash T_Fluchtwegrichtung: -; ash T_Anschlag Gangflügel: -; ash T_Bodendichtung: -; ash T_Lüftungsgitter: 0 m2; ash T_Feuchtebeständigkeit: -; ash T_E_Öffner: TÖ; ash T_Automatik_Antrieb: -; ash T_Sturz: -; ash T_Blatt_Material: -; ash T_Schlossfunktion: -; ash T_Schliesszylinder: -; ash T_Beschlag: KD; ash T_Glasausschnitt: -; ash T_Sonder_Wandmaterial: -; ash T_Anz_Reedkontakte: 0; ash T_Anz_Riegelkontakte: 1; ash T_Schallschutz: -; ash T_Zarge_Material: -; ash T_Bodeneinstand: -; ash T_Raum zugehörigkeit: BS; ash T_Blatt_Farbe: -; ash T_Steuerung (BG): E; ash T_Steuerung (BS): E; Attributset-Objekt: Door; P_ID: 1215Rau0000006917; Allright_Bauteil_ID: 1155Mak0813714999; Abrechnungsart: St; Objektname: Türmakro, -SmartPart
AllplanQuantities - GlassSurface: 2.2736; HeightWindowSillOutside: 0; HeightWindowSillInside: 0; OffsetOpeningBottom: 150; OffsetOpeningTop: 0; OffsetOpeningLeft: 0; OffsetOpeningRight: 0; DeductionOpeningBottom: 150; DeductionOpeningLeft: 50; DeductionOpeningRight: 50; DeductionOpeningTop: 0
Pset_DoorCommon - Status: NEW; IsExternal: no; FireRating: EI2 30; ThermalTransmittance: 0 W/K/m2; HandicapAccessible: no; SmokeStop: yes; SelfClosing: yes; FireExit: no

# IfcDoor: SMT (4)
Type - PredefinedType: DOOR; OperationType: SINGLE_SWING_LEFT; ParameterTakesPrecedence: no
Type - IfcDoorLiningProperties - LiningDepth: 0.08 m; LiningThickness: 0.05 m
OverallWidth: 1.56 m; Material: TI-1F-AG-D-O
AllplanAttributes (SMT) - Gewerk: Zimmer- und Holzbauarbeiten; V6: 0 m; V7: 0 m; V8: 0 m; V9: 0; Programmversion: 3.1; Objektname: Türmakro; Text2: X; Text4: Stahl-Glas-Tür; Bezeichnung: SMT; Material: TI-1F-AG-D-O; Plugin_Bezeichnung: MainObject; Plugin_Objektname: SmartPartCompressed; Glasanteil_berücksichtigen: 100; Version: 7.21; ash T_Sichtschutz: -; ash R_Verweis Wandansicht: -; ash T_Zulage Schachttür: no; ash T_Dichtschließend: no; ash T_Panik: N; ash T_Türschließer: OTS; ash T_Gewerk Los: -; ash T_Erforderl. Durchgangsbreite: 0 m; ash T_Türblatt sichtbar 2D: ja; ash T_Zusatzfunktion Panikschloss: -; ash T_Fluchtwegsicherung: FWS; ash T_Standflügel-Betätigung: -; ash T_Zusatzfunktion Türschließer: -; ash T_Türschließer-Montage: -; ash T_Feststellanlage (FSA): -; ash T_Zusätzliche Rauchmelder: -; ash T_Zusätzl. Anschluss an BMA: -; ash T_Impulsgeber: -; ash T_Sicherheits-Sensorleisten: -; ash T_Anschl. an Zuttrittskontrolle: ZK; ash T_Anschl. an Einbruchmeld.anl.: -; ash T_Klemmschutz: -; ash T_LV-Positions-Nr.: -; ash T_Plan-Nr.: -; ash T_Sonstiges, Bemerkungen: -; ash T_Bodentürstopper: -; ash T_nicht abschließbar: no; ash T_Material Seitenteil: -; ash T_Strahlenschutz: 0.000000; ash T_Kantengeometrie: -; ash T_Kantenmaterial: -; ash T_Blatt_Oberfläche: L; ash T_Erford. Durgangshöhe: 0 m; ash T_Laserschutz: -; ash T_Rammschutz: SB; ash T_Fluchtwegrichtung: A; ash T_Anschlag Gangflügel: -; ash T_Bodendichtung: -; ash T_Lüftungsgitter: 0 m2; ash T_Feuchtebeständigkeit: -; ash T_E_Öffner: TÖ + FTÖ; ash T_Automatik_Antrieb: -; ash T_Blatt_Material: S; ash T_Schlossfunktion: E; ash T_Schliesszylinder: PZ(v); ash T_Beschlag: KD; ash T_Glasausschnitt: -; ash T_Sonder_Wandmaterial: -; ash T_Anz_Reedkontakte: 0; ash T_Anz_Riegelkontakte: 1; ash T_Schallschutz: -; ash T_Bodeneinstand: -; ash T_Raum zugehörigkeit: BS; ash T_Blatt_Farbe: -; ash T_Steuerung (BG): E, H; ash T_Steuerung (BS): E, H; Positionsnummer_Text: S68; Attributset-Objekt: Door; P_ID: 1115Rau0000005069; Abrechnungsart: St
AllplanQuantities - HeightWindowSillOutside: 0; HeightWindowSillInside: 0; OffsetOpeningTop: 0; OffsetOpeningLeft: 0; OffsetOpeningRight: 0; DeductionOpeningBottom: 100; DeductionOpeningLeft: 50; DeductionOpeningRight: 50; DeductionOpeningTop: 50
Pset_DoorCommon - Status: NEW; IsExternal: no; FireRating: EI2 30; ThermalTransmittance: 0 W/K/m2; HandicapAccessible: no; SmokeStop: yes; SelfClosing: yes; FireExit: yes
Name | In | OverallHeight (m) | Ortscode_Geschoßbezeichnung | Text1 | ash T_Zarge_Typ | OKFF | ash T_Tür-Nr. | ash T_Zarge_Material | Allright_Bauteil_ID | GlassSurface | OffsetOpeningBottom
SMT | H2 Ebene +2 | 2.53 | E02 | 132 | BZ | 7.5 | E02-T04-001-132 | - | 1213Mak0813480856 | 2.4072 | 150
SMT | H2 Ebene +2 | 2.53 | E02 | 43 | BZ | 7.5 | E02-T02-001-43 | - | 1213Mak0813567308 | 2.4072 | 150
SMT | H2 Ebene +1 | 2.53 | E00 | 132 | UZ | 0 | E01-T04-001-132 | ST | 1163Mak0814409888 | 2.4072 | 200 | AllplanAttributes (SMT) - ash T_Sturz: -; Pset_DoorCommon - SecurityRating: SA
SMT | H2 Ebene 0 | 2.55 | E00 | 132 | BZ | 0 | E00-T04-001-132 | - | 1113Mak0814024273 | 2.4308 | 200

# IfcDoor: SMT (2)
Type - PredefinedType: DOOR; OperationType: SINGLE_SWING_LEFT; ParameterTakesPrecedence: no
Type - IfcDoorLiningProperties - LiningDepth: 0.18 m; LiningThickness: 0.04 m
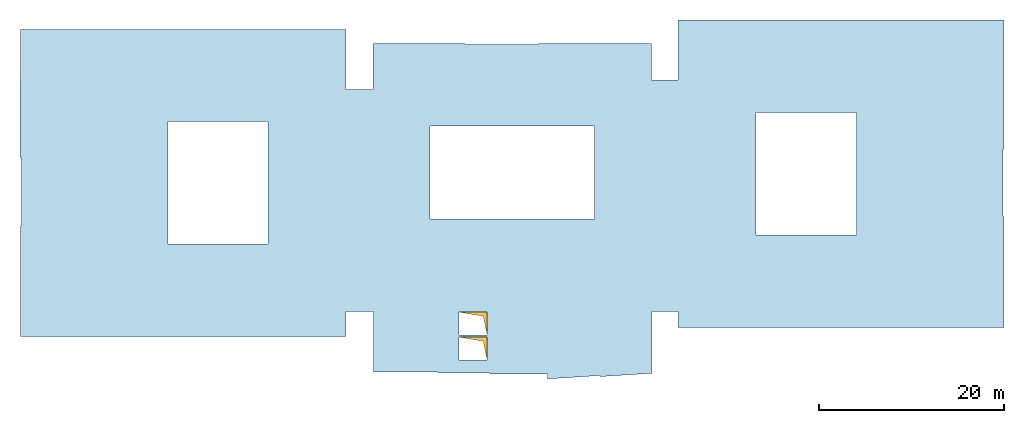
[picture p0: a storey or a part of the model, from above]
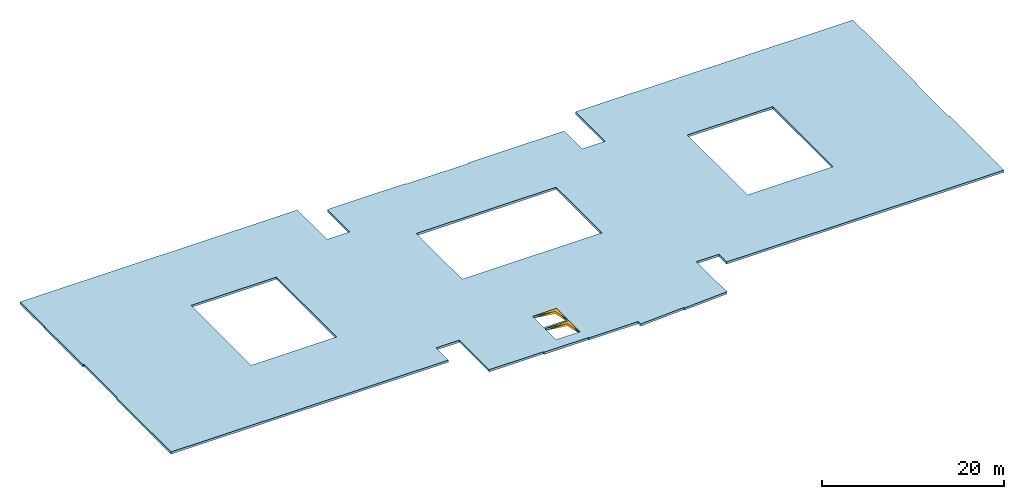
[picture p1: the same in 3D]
Properties of the parts of a building model (IFC4), part 25 of 80

# IfcDoor: SMT (2)
AllplanAttributes (SMT) - Gewerk: Metallbau-, Schlosserarbeiten; V6: 0 m; V7: 0 m; V8: 0 m; V9: 0; Programmversion: 3.1; Objektname: Türmakro; Bezeichnung: SMT; Plugin_Bezeichnung: MainObject; Plugin_Objektname: SmartPartCompressed; Glasanteil_berücksichtigen: 100; Version: 7.21; ash T_Sichtschutz: -; ash R_Verweis Wandansicht: -; ash T_Zulage Schachttür: no; ash T_Panik: -; ash T_Zarge_Typ: UZ; ash T_Türschließer: -; ash T_Gewerk Los: -; ash T_Erforderl. Durchgangsbreite: 0 m; ash T_Türblatt sichtbar 2D: ja; ash T_Zusatzfunktion Panikschloss: -; ash T_Fluchtwegsicherung: -; ash T_Standflügel-Betätigung: -; ash T_Zusatzfunktion Türschließer: -; ash T_Türschließer-Montage: -; ash T_Feststellanlage (FSA): -; ash T_Zusätzliche Rauchmelder: -; ash T_Zusätzl. Anschluss an BMA: -; ash T_Impulsgeber: -; ash T_Sicherheits-Sensorleisten: -; ash T_Anschl. an Einbruchmeld.anl.: -; ash T_Klemmschutz: -; ash T_LV-Positions-Nr.: -; ash T_Plan-Nr.: -; ash T_Sonstiges, Bemerkungen: -; ash T_Bodentürstopper: -; ash T_nicht abschließbar: no; ash T_Material Seitenteil: -; ash T_Kantengeometrie: 2F; ash T_Kantenmaterial: PU; ash T_Blatt_Oberfläche: HPL; ash T_Erford. Durgangshöhe: 0 m; ash T_Rammschutz: BL; ash T_Fluchtwegrichtung: -; ash T_Lüftungsgitter: 0 m2; ash T_Feuchtebeständigkeit: -; ash T_E_Öffner: -; ash T_Automatik_Antrieb: -; ash T_Sturz: -; ash T_Blatt_Material: HO; ash T_Schlossfunktion: -; ash T_Schliesszylinder: PZ; ash T_Glasausschnitt: -; ash T_Sonder_Wandmaterial: -; ash T_Anz_Reedkontakte: 0; ash T_Anz_Riegelkontakte: 0; ash T_Zarge_Material: ST; ash T_Bodeneinstand: -; ash T_Blatt_Farbe: -; Attributset-Objekt: Door; Abrechnungsart: St
AllplanAttributes (TGR 1.6) - Codetext: Typ; V6: 0 m; V7: 0 m; V8: 0 m; V9: 0; Programmversion: 3.1; Objektname: TGR-Makro; Text1: PlanNo.; Bezeichnung: TGR 1.6; Plugin_Bezeichnung: MainObject; Plugin_Objektname: SmartPartCompressed; Version: 1.6; Abrechnungsart: St
AllplanQuantities - GlassSurface: 0; HeightWindowSillOutside: 0; HeightWindowSillInside: 0; OffsetOpeningTop: 0; OffsetOpeningLeft: 0; OffsetOpeningRight: 0; DeductionOpeningBottom: 100; DeductionOpeningLeft: 40; DeductionOpeningRight: 40; DeductionOpeningTop: 40
Pset_DoorCommon - Status: NEW; IsExternal: no; ThermalTransmittance: 0 W/K/m2; HandicapAccessible: no; SmokeStop: no; SelfClosing: no; FireExit: no
Name | In | OverallHeight (m) | OverallWidth (m) | Material = AllplanAttributes (SMT), Material | AllplanAttributes (SMT), Ortscode_Geschoßbezeichnung | Text1 | ash T_Dichtschließend | AllplanAttributes (SMT), OKFF = AllplanAttributes (TGR 1.6), OKFF | ash T_Tür-Nr. | ash T_Bodendichtung | ash T_Beschlag | ash T_Schallschutz | ash T_Raum zugehörigkeit | P_ID | AllplanAttributes (SMT), Allright_Bauteil_ID | Gesamtlänge | ash T_Türprofilnummer | AllplanAttributes (TGR 1.6), Allright_Bauteil_ID | OffsetOpeningBottom
SMT | H2 Ebene +2 | 2.41 | 1.26 | TI-1F-UZ-D | E02 | 154 | no | 7.5 | E02-064-001-154 | - | KD | 37 dB | BGS | 1216Rau0000046860 | 1213Mak0813746546 | 8.36 | 3 | 1213Mak0813746533 | 150 | AllplanAttributes (TGR 1.6) - Ortscode_Geschoßbezeichnung: E02
SMT | H2 Ebene 0 | 2.46 | 1.01 | TI-1F-UZ-ZK | E00 | 133 | yes | 0 | E00-037-001-133 | Ja | DK | 27 dB | BS | 1116Rau0000066366 | 1113Mak0814161188 | 8.26 | 5 | 1113Mak0814161153 | 200 | AllplanAttributes (SMT) - ash T_Anschl. an Zuttrittskontrolle: -; ash T_Strahlenschutz: 0.000000; ash T_Laserschutz: -; ash T_Anschlag Gangflügel: -; Positionsnummer_Text: S68; AllplanAttributes (TGR 1.6) - Positionsnummer_Text: S68

# IfcDoor: SMT (2)
In: H2 Ebene 0
Type - PredefinedType: DOOR; OperationType: SINGLE_SWING_LEFT; ParameterTakesPrecedence: no
Type - IfcDoorLiningProperties - LiningDepth: 0.2 m; LiningThickness: 0.05 m
OverallHeight: 2.72 m; OverallWidth: 1.35 m; Material: TA-1F-AG-D-O
AllplanAttributes (SMT) - Gewerk: Metallbau-, Schlosserarbeiten; V6: 0 m; V7: 0 m; V8: 0 m; V9: 0; Ortscode_Geschoßbezeichnung: E00; Programmversion: 3.0; Objektname: Türmakro; Bezeichnung: SMT; Material: TA-1F-AG-D-O; Plugin_Bezeichnung: MainObject; Plugin_Objektname: SmartPartCompressed; Glasanteil_berücksichtigen: 100; Version: 8.11; ash T_Unterschnitt: -; ash T_Sichtschutz: -; ash R_Verweis Wandansicht: -; ash T_Panik: -; ash T_Zarge_Typ: -; ash T_Türschließer: -; ash T_Gewerk Los: -; ash T_Erforderl. Durchgangsbreite: 0 m; ash T_Türblatt sichtbar 2D: ja; ash T_Zusatzfunktion Panikschloss: -; ash T_Fluchtwegsicherung: -; ash T_Standflügel-Betätigung: -; ash T_Zusatzfunktion Türschließer: -; ash T_Türschließer-Montage: -; ash T_Feststellanlage (FSA): -; ash T_Zusätzliche Rauchmelder: -; ash T_Zusätzl. Anschluss an BMA: -; ash T_Impulsgeber: -; ash T_Sicherheits-Sensorleisten: -; ash T_Anschl. an Zuttrittskontrolle: -; ash T_Anschl. an Einbruchmeld.anl.: -; ash T_Klemmschutz: -; ash T_LV-Positions-Nr.: -; ash T_Plan-Nr.: -; ash T_Sonstiges, Bemerkungen: -; OKFF: 0; ash T_Bodentürstopper: -; ash T_Material Seitenteil: -; ash T_Strahlenschutz: 0.000000; ash T_Kantengeometrie: -; ash T_Kantenmaterial: -; ash T_Blatt_Oberfläche: -; ash T_Erford. Durgangshöhe: 0 m; ash T_Rammschutz: -; ash T_Fluchtwegrichtung: -; ash T_Anschlag Gangflügel: -; ash T_Bodendichtung: -; ash T_Lüftungsgitter: 0 m2; ash T_Feuchtebeständigkeit: -; ash T_E_Öffner: -; ash T_Automatik_Antrieb: -; ash T_Sturz: -; ash T_Blatt_Material: -; ash T_Schlossfunktion: -; ash T_Schliesszylinder: -; ash T_Beschlag: -; ash T_Material Oberlicht: -; ash T_Glasausschnitt: -; ash T_Sonder_Wandmaterial: -; ash T_Anz_Reedkontakte: 0; ash T_Anz_Riegelkontakte: 0; ash T_Schallschutz: -; ash T_Zarge_Material: -; ash T_Bodeneinstand: -; ash T_Raum zugehörigkeit: BS; ash T_Blatt_Farbe: -; g-Wert: 0,35; Positionsnummer_Text: U23; Attributset-Objekt: Door; Abrechnungsart: St
AllplanQuantities - GlassSurface: 2.1146; HeightWindowSillOutside: 0; HeightWindowSillInside: 0; OffsetOpeningBottom: 200; OffsetOpeningTop: 0; OffsetOpeningLeft: 0; OffsetOpeningRight: 0; DeductionOpeningBottom: 150; DeductionOpeningLeft: 50; DeductionOpeningRight: 50; DeductionOpeningTop: 50
Pset_DoorCommon - Status: NEW; IsExternal: yes; FireRating: 0; ThermalTransmittance: 1 W/K/m2; AcousticRating: -; SecurityRating: RC 1; Reference: T_Typ15
Name | Text1 | ash T_Tür-Nr. | P_ID | Allright_Bauteil_ID
SMT | 11 | TA-1FR-D-E00-L004 | 1115Rau0000005201 | 1105Mak0000085837
SMT | 5 | TA-1FR-D-E00-L001 | 1115Rau0000005169 | 1105Mak0000085275

# IfcDoor: SMT (2)
Type - PredefinedType: DOOR; OperationType: SINGLE_SWING_LEFT; ParameterTakesPrecedence: no
Type - IfcDoorLiningProperties - LiningDepth: 0.262 m; LiningThickness: 0.04 m
OverallWidth: 1.26 m; Material: TI-1F-UZ-ZK
AllplanAttributes (SMT) - Gewerk: Metallbau-, Schlosserarbeiten; V6: 0 m; V7: 0 m; V8: 0 m; V9: 0; Programmversion: 3.1; Objektname: Türmakro; Text1: 87; Bezeichnung: SMT; Material: TI-1F-UZ-ZK; Plugin_Bezeichnung: MainObject; Plugin_Objektname: SmartPartCompressed; Glasanteil_berücksichtigen: 100; Version: 7.21; ash T_Sichtschutz: -; ash R_Verweis Wandansicht: -; ash T_Zulage Schachttür: no; ash T_Dichtschließend: no; ash T_Panik: -; ash T_Zarge_Typ: UZ; ash T_Türschließer: -; ash T_Gewerk Los: -; ash T_Erforderl. Durchgangsbreite: 0 m; ash T_Türblatt sichtbar 2D: ja; ash T_Zusatzfunktion Panikschloss: -; ash T_Fluchtwegsicherung: -; ash T_Standflügel-Betätigung: -; ash T_Zusatzfunktion Türschließer: -; ash T_Türschließer-Montage: -; ash T_Feststellanlage (FSA): FL; ash T_Zusätzliche Rauchmelder: -; ash T_Zusätzl. Anschluss an BMA: -; ash T_Impulsgeber: -; ash T_Sicherheits-Sensorleisten: -; ash T_Anschl. an Einbruchmeld.anl.: -; ash T_Klemmschutz: -; ash T_LV-Positions-Nr.: -; ash T_Plan-Nr.: -; ash T_Sonstiges, Bemerkungen: -; ash T_Bodentürstopper: -; ash T_nicht abschließbar: no; ash T_Material Seitenteil: -; ash T_Strahlenschutz: 0.000000; ash T_Kantengeometrie: 2F; ash T_Kantenmaterial: PU; ash T_Blatt_Oberfläche: HPL; ash T_Erford. Durgangshöhe: 0 m; ash T_Rammschutz: BL; ash T_Fluchtwegrichtung: -; ash T_Anschlag Gangflügel: -; ash T_Bodendichtung: -; ash T_Lüftungsgitter: 0 m2; ash T_Feuchtebeständigkeit: -; ash T_E_Öffner: -; ash T_Automatik_Antrieb: -; ash T_Sturz: -; ash T_Blatt_Material: HO; ash T_Schlossfunktion: -; ash T_Schliesszylinder: PZ; ash T_Beschlag: KD; ash T_Glasausschnitt: -; ash T_Sonder_Wandmaterial: -; ash T_Anz_Reedkontakte: 0; ash T_Anz_Riegelkontakte: 0; ash T_Schallschutz: -; ash T_Zarge_Material: ST; ash T_Bodeneinstand: -; ash T_Raum zugehörigkeit: BGS; ash T_Blatt_Farbe: -; Attributset-Objekt: Door; Abrechnungsart: St
AllplanQuantities - GlassSurface: 0; HeightWindowSillOutside: 0; HeightWindowSillInside: 0; OffsetOpeningTop: 0; OffsetOpeningLeft: 0; OffsetOpeningRight: 0; DeductionOpeningBottom: 100; DeductionOpeningLeft: 40; DeductionOpeningRight: 40; DeductionOpeningTop: 40
Pset_DoorCommon - Status: NEW; IsExternal: no; FireRating: EI2 30; ThermalTransmittance: 0 W/K/m2; HandicapAccessible: no; SmokeStop: yes; SelfClosing: yes; FireExit: no
Name | In | OverallHeight (m) | Ortscode_Geschoßbezeichnung | OKFF | ash T_Tür-Nr. | Positionsnummer_Text | P_ID | Allright_Bauteil_ID | OffsetOpeningBottom
SMT | H2 Ebene +1 | 2.41 | E01 | 3.75 | E01-049-001-87 | U100 | 1165Rau0000004701 | 1163Mak0812551705 | 150
SMT | H2 Ebene 0 | 2.46 | E00 | 0 | E00-049-001-87 | S68 | 1115Rau0000005053 | 1113Mak0812551705 | 200

# IfcDoor: SMT (2)
Type - PredefinedType: DOOR; OperationType: SINGLE_SWING_LEFT; ParameterTakesPrecedence: no
Type - IfcDoorLiningProperties - LiningDepth: 0.302 m; LiningThickness: 0.04 m
OverallHeight: 2.41 m; Material: TI-1F-UZ-D
AllplanAttributes (SMT) - V6: 0 m; V7: 0 m; V8: 0 m; V9: 0; Objektname: Türmakro; Bezeichnung: SMT; Material: TI-1F-UZ-D; Plugin_Bezeichnung: MainObject; Plugin_Objektname: SmartPartCompressed; Glasanteil_berücksichtigen: 100; ash T_Zulage Schachttür: no; ash T_Zarge_Typ: UZ; ash T_Erforderl. Durchgangsbreite: 0 m; ash T_Türblatt sichtbar 2D: ja; ash T_nicht abschließbar: no; ash T_Erford. Durgangshöhe: 0 m; ash T_Lüftungsgitter: 0 m2; ash T_Schliesszylinder: PZ; ash T_Anz_Reedkontakte: 0; ash T_Anz_Riegelkontakte: 0; ash T_Zarge_Material: ST; ash T_Raum zugehörigkeit: BS; Attributset-Objekt: Door; Abrechnungsart: St
AllplanQuantities - GlassSurface: 0; HeightWindowSillOutside: 0; HeightWindowSillInside: 0; OffsetOpeningBottom: 150; OffsetOpeningTop: 0; OffsetOpeningLeft: 0; OffsetOpeningRight: 0; DeductionOpeningBottom: 100; DeductionOpeningLeft: 40; DeductionOpeningRight: 40; DeductionOpeningTop: 40
Pset_DoorCommon - Status: NEW; IsExternal: no; ThermalTransmittance: 0 W/K/m2; HandicapAccessible: no; FireExit: no
Name | In | OverallWidth (m) | Gewerk | Ortscode_Geschoßbezeichnung | Programmversion | Text1 | Version | ash T_Dichtschließend | OKFF | ash T_Tür-Nr. | ash T_Kantengeometrie | ash T_Blatt_Oberfläche | ash T_Blatt_Material | ash T_Beschlag | ash T_Schallschutz | P_ID | Allright_Bauteil_ID | SmokeStop = SelfClosing
SMT | H2 Ebene +3 | 1.01 | Metallbau-, Schlosserarbeiten | E03 | 3.0 | 28 | 8.11 | yes | 11.25 | E03-012-001-28 | LF | L | ST | DK | 32 dB | 1266Rau0000015498 | 1263Mak0812915388 | no | AllplanAttributes (SMT) - Text2: -; ash T_Strahlenschutz: 0.000000; ash T_Anschlag Gangflügel: -
SMT | H2 Ebene +2 | 1.135 | Zimmer- und Holzbauarbeiten | E02 | 3.1 | 76 | 7.21 | no | 7.5 | E02-004-002-76 | 2F | HPL | HO | DD | - | 1216Rau0000046405 | 1213Mak0813004596 | yes | AllplanAttributes (SMT) - ash T_Sichtschutz: -; ash R_Verweis Wandansicht: -; ash T_Panik: -; ash T_Türschließer: OTS; ash T_Gewerk Los: -; ash T_Zusatzfunktion Panikschloss: -; ash T_Fluchtwegsicherung: -; ash T_Standflügel-Betätigung: -; ash T_Zusatzfunktion Türschließer: -; ash T_Türschließer-Montage: -; ash T_Feststellanlage (FSA): -; ash T_Zusätzliche Rauchmelder: -; ash T_Zusätzl. Anschluss an BMA: -; ash T_Impulsgeber: -; ash T_Sicherheits-Sensorleisten: -; ash T_Anschl. an Einbruchmeld.anl.: -; ash T_Klemmschutz: -; ash T_LV-Positions-Nr.: -; ash T_Plan-Nr.: -; ash T_Sonstiges, Bemerkungen: -; ash T_Bodentürstopper: -; ash T_Material Seitenteil: -; ash T_Kantenmaterial: PU; ash T_Rammschutz: BL; ash T_Fluchtwegrichtung: -; ash T_Bodendichtung: Ja; ash T_Feuchtebeständigkeit: -; ash T_E_Öffner: -; ash T_Automatik_Antrieb: -; ash T_Sturz: -; ash T_Schlossfunktion: -; ash T_Glasausschnitt: -; ash T_Sonder_Wandmaterial: -; ash T_Bodeneinstand: -; ash T_Blatt_Farbe: -; Pset_DoorCommon - FireRating: EI2 30

# IfcDoor: SMT
In: H2 Ebene +3
Type - PredefinedType: DOOR; OperationType: SINGLE_SWING_LEFT; ParameterTakesPrecedence: no
Type - IfcDoorLiningProperties - LiningDepth: 0.32 m; LiningThickness: 0.04 m
OverallHeight: 1.95 m; OverallWidth: 1.01 m; Material: TI-1F-UZ-D
AllplanAttributes (SMT) - Gewerk: Metallbau-, Schlosserarbeiten; V6: 0 m; V7: 0 m; V8: 0 m; V9: 0; Ortscode_Geschoßbezeichnung: E03; Programmversion: 3.1; Objektname: Türmakro; Text1: 45; Text2: -; Bezeichnung: SMT; Material: TI-1F-UZ-D; Plugin_Bezeichnung: MainObject; Plugin_Objektname: SmartPartCompressed; Glasanteil_berücksichtigen: 100; Version: 7.21; ash T_Zulage Schachttür: no; ash T_Dichtschließend: no; ash T_Zarge_Typ: UZ; ash T_Türschließer: OTS; ash T_Erforderl. Durchgangsbreite: 0 m; ash T_Türblatt sichtbar 2D: ja; ash T_Feststellanlage (FSA): -; OKFF: 11.25; ash T_nicht abschließbar: no; ash T_Strahlenschutz: 0.000000; ash T_Tür-Nr.: E03-020-001-45; ash T_Kantengeometrie: 2F; ash T_Kantenmaterial: PU; ash T_Blatt_Oberfläche: HPL; ash T_Erford. Durgangshöhe: 0 m; ash T_Anschlag Gangflügel: -; ash T_Lüftungsgitter: 0 m2; ash T_Blatt_Material: HO; ash T_Schliesszylinder: PZ; ash T_Beschlag: DK; ash T_Anz_Reedkontakte: 0; ash T_Anz_Riegelkontakte: 0; ash T_Schallschutz: -; ash T_Zarge_Material: ST; ash T_Raum zugehörigkeit: BS; Attributset-Objekt: Door; P_ID: 1266Rau0000012867; Allright_Bauteil_ID: 1263Mak0812605361; Abrechnungsart: St
AllplanQuantities - GlassSurface: 0; HeightWindowSillOutside: 0; HeightWindowSillInside: 0; OffsetOpeningBottom: 150; OffsetOpeningTop: 0; OffsetOpeningLeft: 0; OffsetOpeningRight: 0; DeductionOpeningBottom: 100; DeductionOpeningLeft: 40; DeductionOpeningRight: 40; DeductionOpeningTop: 40
Pset_DoorCommon - Status: NEW; IsExternal: no; FireRating: EI2 30; ThermalTransmittance: 0 W/K/m2; HandicapAccessible: no; SmokeStop: yes; SelfClosing: yes; FireExit: no

# IfcDoor: SMT (10)
In: H2 Ebene +3
Type - PredefinedType: DOOR; OperationType: SINGLE_SWING_RIGHT; ParameterTakesPrecedence: no
OverallHeight: 2.16 m; OverallWidth: 0.6 m; Material: TI-1F-D
AllplanAttributes (SMT) - Gewerk: Metallbau-, Schlosserarbeiten; V6: 0 m; V7: 0 m; V8: 0 m; V9: 0; Ortscode_Geschoßbezeichnung: E03; Programmversion: 3.1; Objektname: Türmakro; Text2: -; Bezeichnung: SMT; Material: TI-1F-D; Plugin_Bezeichnung: MainObject; Plugin_Objektname: SmartPartCompressed; Glasanteil_berücksichtigen: 100; Version: 7.21; ash T_Unterschnitt: -; ash T_Zarge_Typ: UZ; ash T_Erforderl. Durchgangsbreite: 0 m; ash T_Türblatt sichtbar 2D: ja; OKFF: 11.25; ash T_Kantengeometrie: LF; ash T_Blatt_Oberfläche: L; ash T_Erford. Durgangshöhe: 0 m; ash T_Lüftungsgitter: 0 m2; ash T_Blatt_Material: ST; ash T_Schliesszylinder: WC; ash T_Beschlag: DD; ash T_Anz_Reedkontakte: 0; ash T_Anz_Riegelkontakte: 0; ash T_Schallschutz: -; ash T_Zarge_Material: ST; ash T_Raum zugehörigkeit: BS; Attributset-Objekt: Door; Abrechnungsart: St
AllplanQuantities - GlassSurface: 0; HeightWindowSillOutside: 0; HeightWindowSillInside: 0; OffsetOpeningBottom: 150; OffsetOpeningTop: 0; OffsetOpeningLeft: 0; OffsetOpeningRight: 0; DeductionOpeningBottom: 150; DeductionOpeningLeft: 0; DeductionOpeningRight: 0; DeductionOpeningTop: 0
Pset_DoorCommon - Status: NEW; IsExternal: no; ThermalTransmittance: 0 W/K/m2; HandicapAccessible: no; FireExit: no
Name | Text1 | ash T_Tür-Nr. | P_ID | Allright_Bauteil_ID
SMT | 18j | E03-009-007-18j | 1263Tür0812772219 | 1263Mak0812772220
SMT | 18i | E03-009-008-18i | 1263Tür0812772195 | 1263Mak0812772196
SMT | 18f | E03-009-003-18f | 1263Tür0812772189 | 1263Mak0812772190
SMT | 18g | E03-009-010-18g | 1263Tür0812772186 | 1263Mak0812772187
SMT | 18h | E03-009-004-18h | 1263Tür0812772192 | 1263Mak0812772193
SMT | 18a | E03-009-009-18a | 1263Tür0812772078 | 1263Mak0812772086
SMT | 18b | E03-009-011-18b | 1263Tür0812772067 | 1263Mak0812772075
SMT | 18d | E03-009-006-18d | 1263Tür0812771735 | 1263Mak0812771680
SMT | 18c | E03-009-012-18c | 1263Tür0812772056 | 1263Mak0812772064
SMT | 18e | E03-009-005-18e | 1263Tür0812772045 | 1263Mak0812772046

# IfcDoor: SMT (2)
In: H2 Ebene 0
Type - PredefinedType: DOOR; OperationType: SINGLE_SWING_RIGHT; ParameterTakesPrecedence: no
Type - IfcDoorLiningProperties - LiningDepth: 0.055 m; LiningThickness: 0.04 m
OverallHeight: 2.46 m; OverallWidth: 1.26 m; Material: TI-1F-UZ-ZK
AllplanAttributes (SMT) - Gewerk: Zimmer- und Holzbauarbeiten; V6: 0 m; V7: 0 m; V8: 0 m; V9: 0; Ortscode_Geschoßbezeichnung: E00; Programmversion: 3.1; Objektname: Türmakro; Bezeichnung: SMT; Material: TI-1F-UZ-ZK; Plugin_Bezeichnung: MainObject; Plugin_Objektname: SmartPartCompressed; Glasanteil_berücksichtigen: 100; Version: 7.21; ash T_Sichtschutz: -; ash R_Verweis Wandansicht: -; ash T_Zulage Schachttür: no; ash T_Dichtschließend: no; ash T_Panik: -; ash T_Zarge_Typ: UZ; ash T_Türschließer: OTS; ash T_Gewerk Los: -; ash T_Erforderl. Durchgangsbreite: 0 m; ash T_Türblatt sichtbar 2D: ja; ash T_Zusatzfunktion Panikschloss: -; ash T_Fluchtwegsicherung: -; ash T_Standflügel-Betätigung: -; ash T_Zusatzfunktion Türschließer: -; ash T_Türschließer-Montage: -; ash T_Feststellanlage (FSA): -; ash T_Zusätzliche Rauchmelder: -; ash T_Zusätzl. Anschluss an BMA: -; ash T_Impulsgeber: -; ash T_Sicherheits-Sensorleisten: -; ash T_Anschl. an Zuttrittskontrolle: -; ash T_Anschl. an Einbruchmeld.anl.: -; ash T_Klemmschutz: -; ash T_LV-Positions-Nr.: -; ash T_Plan-Nr.: -; ash T_Sonstiges, Bemerkungen: -; OKFF: 0; ash T_Bodentürstopper: -; ash T_nicht abschließbar: no; ash T_Material Seitenteil: -; ash T_Strahlenschutz: 0.000000; ash T_Kantengeometrie: 2F; ash T_Kantenmaterial: PU; ash T_Blatt_Oberfläche: HPL; ash T_Erford. Durgangshöhe: 0 m; ash T_Laserschutz: -; ash T_Rammschutz: BL; ash T_Fluchtwegrichtung: -; ash T_Anschlag Gangflügel: -; ash T_Bodendichtung: -; ash T_Lüftungsgitter: 0 m2; ash T_Feuchtebeständigkeit: -; ash T_E_Öffner: -; ash T_Automatik_Antrieb: -; ash T_Sturz: -; ash T_Blatt_Material: HO; ash T_Schlossfunktion: -; ash T_Schliesszylinder: PZ; ash T_Beschlag: DK; ash T_Glasausschnitt: -; ash T_Sonder_Wandmaterial: -; ash T_Anz_Reedkontakte: 0; ash T_Anz_Riegelkontakte: 0; ash T_Schallschutz: -; ash T_Zarge_Material: ST; ash T_Bodeneinstand: -; ash T_Raum zugehörigkeit: BS; ash T_Blatt_Farbe: -; Positionsnummer_Text: S68; Attributset-Objekt: Door; Abrechnungsart: St
AllplanQuantities - GlassSurface: 0; HeightWindowSillOutside: 0; HeightWindowSillInside: 0; OffsetOpeningBottom: 200; OffsetOpeningTop: 0; OffsetOpeningLeft: 0; OffsetOpeningRight: 0; DeductionOpeningBottom: 100; DeductionOpeningLeft: 40; DeductionOpeningRight: 40; DeductionOpeningTop: 40
Pset_DoorCommon - Status: NEW; IsExternal: no; FireRating: EI2 30; ThermalTransmittance: 0 W/K/m2; HandicapAccessible: no; SmokeStop: yes; SelfClosing: yes; FireExit: no
Name | Text1 | ash T_Tür-Nr. | P_ID | Allright_Bauteil_ID
SMT | 19 | E00-001-001-19 | 1116Rau0000065702 | 1113Mak0812442215
SMT | 20 | E00-002-001-20 | 1116Rau0000065699 | 1113Mak0812442211

# IfcDoor: SMT (13)
Type - PredefinedType: DOOR; OperationType: SINGLE_SWING_RIGHT; ParameterTakesPrecedence: no
Type - IfcDoorLiningProperties - LiningDepth: 0.07 m; LiningThickness: 0.04 m
AllplanAttributes (SMT) - Gewerk: Zimmer- und Holzbauarbeiten; V6: 0 m; V7: 0 m; V8: 0 m; V9: 0; Programmversion: 3.1; Objektname: Türmakro; Bezeichnung: SMT; Plugin_Bezeichnung: MainObject; Plugin_Objektname: SmartPartCompressed; Glasanteil_berücksichtigen: 100; Version: 7.21; ash T_Sichtschutz: -; ash R_Verweis Wandansicht: -; ash T_Zulage Schachttür: no; ash T_Panik: -; ash T_Gewerk Los: -; ash T_Erforderl. Durchgangsbreite: 0 m; ash T_Türblatt sichtbar 2D: ja; ash T_Zusatzfunktion Panikschloss: -; ash T_Fluchtwegsicherung: -; ash T_Standflügel-Betätigung: -; ash T_Zusatzfunktion Türschließer: -; ash T_Türschließer-Montage: -; ash T_Feststellanlage (FSA): -; ash T_Zusätzliche Rauchmelder: -; ash T_Zusätzl. Anschluss an BMA: -; ash T_Impulsgeber: -; ash T_Sicherheits-Sensorleisten: -; ash T_Anschl. an Einbruchmeld.anl.: -; ash T_Klemmschutz: -; ash T_LV-Positions-Nr.: -; ash T_Plan-Nr.: -; ash T_Sonstiges, Bemerkungen: -; ash T_Bodentürstopper: -; ash T_nicht abschließbar: no; ash T_Material Seitenteil: -; ash T_Strahlenschutz: 0.000000; ash T_Kantengeometrie: 2F; ash T_Kantenmaterial: PU; ash T_Blatt_Oberfläche: HPL; ash T_Erford. Durgangshöhe: 0 m; ash T_Rammschutz: BL; ash T_Fluchtwegrichtung: -; ash T_Anschlag Gangflügel: -; ash T_Lüftungsgitter: 0 m2; ash T_Feuchtebeständigkeit: -; ash T_E_Öffner: -; ash T_Automatik_Antrieb: -; ash T_Blatt_Material: HO; ash T_Schlossfunktion: -; ash T_Schliesszylinder: PZ; ash T_Glasausschnitt: -; ash T_Sonder_Wandmaterial: -; ash T_Anz_Reedkontakte: 0; ash T_Anz_Riegelkontakte: 0; ash T_Bodeneinstand: -; ash T_Blatt_Farbe: -; Attributset-Objekt: Door; Abrechnungsart: St
AllplanQuantities - GlassSurface: 0; HeightWindowSillOutside: 0; HeightWindowSillInside: 0; OffsetOpeningTop: 0; OffsetOpeningLeft: 0; OffsetOpeningRight: 0; DeductionOpeningBottom: 100; DeductionOpeningLeft: 40; DeductionOpeningRight: 40; DeductionOpeningTop: 40
Pset_DoorCommon - Status: NEW; IsExternal: no; ThermalTransmittance: 0 W/K/m2; HandicapAccessible: no; FireExit: no
Name | In | OverallHeight (m) | OverallWidth (m) | Material = AllplanAttributes (SMT), Material | Ortscode_Geschoßbezeichnung | Text1 | ash T_Dichtschließend | ash T_Zarge_Typ | ash T_Türschließer | OKFF | ash T_Tür-Nr. | ash T_Bodendichtung | ash T_Sturz | ash T_Beschlag | ash T_Schallschutz | ash T_Zarge_Material | ash T_Raum zugehörigkeit | Positionsnummer_Text | P_ID | Allright_Bauteil_ID | OffsetOpeningBottom | SmokeStop = SelfClosing
SMT | H2 Ebene +1 | 2.41 | 1.01 | TI-1F-UZ-ZK | E01 | 126 | yes | UZ | - | 3.75 | E01-085-001-126 | Ja | - | DK | 27 dB | ST | BS | U100 | 1166Rau0000034342 | 1163Mak0814182432 | 150 | no
SMT | H2 Ebene +1 | 2.41 | 1.135 | TI-1F-UZ-ZK | E01 | 98 | no | UZ | OTS | 3.75 | E01-065-001-98 | - | - | DK | - | ST | BS | U100 | 1166Rau0000034235 | 1163Mak0812543260 | 150 | yes | Pset_DoorCommon - FireRating: EI2 30
SMT | H2 Ebene +1 | 2.41 | 1.135 | TI-1F-UZ-D | E01 | 97 | no | UZ | - | 3.75 | E01-066-001-97 | Ja | - | DD | - | ST | BGS | U100 | 1165Rau0000004819 | 1163Mak0812438160 | 150 | no
SMT | H2 Ebene +1 | 2.41 | 1.01 | TI-1F-UZ-ZK | E01 | 124 | yes | UZ | - | 3.75 | E01-086-001-124 | Ja | - | DK | 27 dB | ST | BS | U100 | 1166Rau0000034355 | 1163Mak0814183045 | 150 | no
SMT | H2 Ebene +1 | 2.41 | 1.01 | TI-1F-UZ-ZK | E01 | 131 | yes | BZ | - | 3.75 | E01-083-001-131 | Ja |  | DK | 27 dB | - | BS | U100 | 1166Rau0000034329 | 1163Mak0812492975 | 150 | no
SMT | H2 Ebene +1 | 2.41 | 1.01 | TI-1F-UZ-ZK | E01 | 129 | yes | UZ | - | 3.75 | E01-084-001-129 | Ja | - | DK | 27 dB | ST | BS | U100 | 1166Rau0000034718 | 1163Mak0814179163 | 150 | no
SMT | H2 Ebene +1 | 2.41 | 1.01 | TI-1F-UZ-ZK | E01 | 42 | yes | UZ | - | 3.75 | E01-036-001-42 | Ja | - | DK | 27 dB | ST | BS | U100 | 1166Rau0000033499 | 1163Mak0812443195 | 150 | no
SMT | H2 Ebene +1 | 2.41 | 1.01 | TI-1F-UZ-ZK | E01 | 48 | yes | UZ | - | 3.75 | E01-034-001-48 | Ja | - | DK | 27 dB | ST | BS | U100 | 1166Rau0000033486 | 1163Mak0814723856 | 150 | no
SMT | H2 Ebene +1 | 2.41 | 1.01 | TI-1F-UZ-ZK | E01 | 50 | yes | UZ | - | 3.75 | E01-033-001-50 | Ja | - | DK | 27 dB | ST | BS | U100 | 1166Rau0000033473 | 1163Mak0814723860 | 150 | no
SMT | H2 Ebene +1 | 2.41 | 1.01 | TI-1F-UZ-ZK | E01 | 45 | yes | UZ | - | 3.75 | E01-035-001-45 | Ja | - | DK | 27 dB | ST | BS | U100 | 1166Rau0000034731 | 1163Mak0814566109 | 150 | no
SMT | H2 Ebene 0 | 2.46 | 1.135 | TI-1F-UZ-D | E00 | 97 | no | UZ | - | 0 | E00-066-001-97 | Ja | - | DD | - | ST | BGS | S68 | 1115Rau0000005220 | 1113Mak0812438160 | 200 | no
SMT | H2 Ebene 0 | 2.46 | 1.01 | TI-1F-UZ-ZK | E00 | 131 | yes | UZ | - | 0 | E00-083-001-131 | Ja | - | DK | 27 dB | ST | BS | S68 | 1116Rau0000066707 | 1113Mak0812492975 | 200 | no
SMT | H2 Ebene 0 | 2.46 | 1.135 | TI-1F-UZ-ZK | E00 | 98 | no | UZ | OTS | 0 | E00-065-001-98 | - | - | DK | - | ST | BS | S68 | 1116Rau0000066789 | 1113Mak0812543260 | 200 | yes | Pset_DoorCommon - FireRating: EI2 30

# IfcDoor: SMT (2)
In: H2 Ebene 0
Type - PredefinedType: DOOR; OperationType: SINGLE_SWING_RIGHT; ParameterTakesPrecedence: no
Type - IfcDoorLiningProperties - LiningDepth: 0.07 m; LiningThickness: 0.05 m
OverallHeight: 2.67 m; OverallWidth: 1.25 m; Material: TA-1F-AG-D-O
AllplanAttributes (SMT) - Gewerk: Metallbau-, Schlosserarbeiten; V6: 0 m; V7: 0 m; V8: 0 m; V9: 0; Ortscode_Geschoßbezeichnung: E00; Programmversion: 3.0; Objektname: Türmakro; Text1: 8; Bezeichnung: SMT; Material: TA-1F-AG-D-O; Plugin_Bezeichnung: MainObject; Plugin_Objektname: SmartPartCompressed; Glasanteil_berücksichtigen: 100; Version: 8.11; ash T_Unterschnitt: -; ash T_Sichtschutz: -; ash R_Verweis Wandansicht: -; ash T_Panik: -; ash T_Zarge_Typ: -; ash T_Türschließer: -; ash T_Gewerk Los: -; ash T_Erforderl. Durchgangsbreite: 0 m; ash T_Türblatt sichtbar 2D: ja; ash T_Zusatzfunktion Panikschloss: -; ash T_Fluchtwegsicherung: -; ash T_Standflügel-Betätigung: -; ash T_Zusatzfunktion Türschließer: -; ash T_Türschließer-Montage: -; ash T_Feststellanlage (FSA): -; ash T_Zusätzliche Rauchmelder: -; ash T_Zusätzl. Anschluss an BMA: -; ash T_Impulsgeber: -; ash T_Sicherheits-Sensorleisten: -; ash T_Anschl. an Zuttrittskontrolle: -; ash T_Anschl. an Einbruchmeld.anl.: -; ash T_Klemmschutz: -; ash T_LV-Positions-Nr.: -; ash T_Plan-Nr.: -; ash T_Sonstiges, Bemerkungen: -; OKFF: 0; ash T_Bodentürstopper: -; ash T_Material Seitenteil: -; ash T_Strahlenschutz: 0.000000; ash T_Kantengeometrie: -; ash T_Kantenmaterial: -; ash T_Blatt_Oberfläche: -; ash T_Erford. Durgangshöhe: 0 m; ash T_Rammschutz: -; ash T_Fluchtwegrichtung: -; ash T_Anschlag Gangflügel: -; ash T_Bodendichtung: -; ash T_Lüftungsgitter: 0 m2; ash T_Feuchtebeständigkeit: -; ash T_E_Öffner: -; ash T_Automatik_Antrieb: -; ash T_Sturz: -; ash T_Blatt_Material: -; ash T_Schlossfunktion: -; ash T_Schliesszylinder: -; ash T_Beschlag: -; ash T_Material Oberlicht: -; ash T_Glasausschnitt: -; ash T_Sonder_Wandmaterial: -; ash T_Anz_Reedkontakte: 0; ash T_Anz_Riegelkontakte: 0; ash T_Schallschutz: -; ash T_Zarge_Material: -; ash T_Bodeneinstand: -; ash T_Raum zugehörigkeit: BS; ash T_Blatt_Farbe: -; g-Wert: 0,35; Positionsnummer_Text: U23; Attributset-Objekt: Door; P_ID: 1115Rau0000005053; Abrechnungsart: St
AllplanQuantities - GlassSurface: 2.2995; HeightWindowSillOutside: 0; HeightWindowSillInside: 0; OffsetOpeningBottom: 200; OffsetOpeningTop: 0; OffsetOpeningLeft: 0; OffsetOpeningRight: 0; DeductionOpeningBottom: 200; DeductionOpeningLeft: 50; DeductionOpeningRight: 50; DeductionOpeningTop: 50
Pset_DoorCommon - Status: NEW; IsExternal: yes; FireRating: 0; ThermalTransmittance: 1 W/K/m2; AcousticRating: -
Name | ash T_Tür-Nr. | Allright_Bauteil_ID | SecurityRating | Reference
SMT | TA-1FL-D-2S-E00-L006 | 1105Mak2005789814 | RC 1 | T_Typ13
SMT | TA-1FL-D-2S-E00-L002 | 1105Mak2005786145 | - | T_Typ14

# IfcDoor: SMT (4)
Type - PredefinedType: DOOR; OperationType: SINGLE_SWING_RIGHT; ParameterTakesPrecedence: no
Type - IfcDoorLiningProperties - LiningDepth: 0.079 m; LiningThickness: 0.05 m
AllplanAttributes (SMT) - Gewerk: Metallbau-, Schlosserarbeiten; V6: 0 m; V7: 0 m; V8: 0 m; V9: 0; Objektname: Türmakro; Bezeichnung: SMT; Plugin_Bezeichnung: MainObject; Plugin_Objektname: SmartPartCompressed; Glasanteil_berücksichtigen: 100; ash T_Zulage Schachttür: no; ash T_Dichtschließend: no; ash T_Erforderl. Durchgangsbreite: 0 m; ash T_Türblatt sichtbar 2D: ja; ash T_Zusatzfunktion Panikschloss: -; ash T_Fluchtwegsicherung: -; ash T_Standflügel-Betätigung: -; ash T_Zusatzfunktion Türschließer: -; ash T_Türschließer-Montage: -; ash T_Zusätzliche Rauchmelder: -; ash T_Zusätzl. Anschluss an BMA: -; ash T_Impulsgeber: -; ash T_Sicherheits-Sensorleisten: -; ash T_Anschl. an Zuttrittskontrolle: -; ash T_Anschl. an Einbruchmeld.anl.: -; ash T_Klemmschutz: -; ash T_Bodentürstopper: -; ash T_nicht abschließbar: no; ash T_Strahlenschutz: 0.000000; ash T_Kantenmaterial: -; ash T_Erford. Durgangshöhe: 0 m; ash T_Laserschutz: -; ash T_Rammschutz: -; ash T_Fluchtwegrichtung: -; ash T_Anschlag Gangflügel: -; ash T_Bodendichtung: -; ash T_Lüftungsgitter: 0 m2; ash T_Feuchtebeständigkeit: -; ash T_E_Öffner: -; ash T_Automatik_Antrieb: -; ash T_Sturz: -; ash T_Schliesszylinder: PZ; ash T_Beschlag: KD; ash T_Anz_Reedkontakte: 0; ash T_Schallschutz: -; ash T_Bodeneinstand: -; ash T_Raum zugehörigkeit: BS; Attributset-Objekt: Door; Abrechnungsart: St
AllplanQuantities - HeightWindowSillOutside: 0; HeightWindowSillInside: 0; OffsetOpeningTop: 0; OffsetOpeningLeft: 0; OffsetOpeningRight: 0; DeductionOpeningLeft: 50; DeductionOpeningRight: 50; DeductionOpeningTop: 50
Pset_DoorCommon - Status: NEW
Name | In | OverallHeight (m) | OverallWidth (m) | Material = AllplanAttributes (SMT), Material | Ortscode_Geschoßbezeichnung | Programmversion | Text1 | Version | ash T_Panik | ash T_Zarge_Typ | ash T_Türschließer | ash T_Feststellanlage (FSA) | OKFF | ash T_Tür-Nr. | ash T_Kantengeometrie | ash T_Blatt_Oberfläche | ash T_Blatt_Material | ash T_Anz_Riegelkontakte | ash T_Zarge_Material | P_ID | Allright_Bauteil_ID | GlassSurface | OffsetOpeningBottom | DeductionOpeningBottom | IsExternal | FireRating | ThermalTransmittance (W/K/m2) | SmokeStop = SelfClosing | SecurityRating | ash T_Sichtschutz = ash T_Gewerk Los = ash T_LV-Positions-Nr. = ash T_Plan-Nr. = ash T_Sonstiges, Bemerkungen = ash T_Türtyp Nr. = ash T_Material Seitenteil = ash T_Material Oberlicht = ash T_Glasausschnitt = ash T_Sonder_Wandmaterial = ash T_Blatt_Farbe | ash T_Schlossfunktion | g-Wert | Positionsnummer_Text | AcousticRating | Reference
SMT | H2 Ebene +3 | 2.53 | 1.50001 | TI-1F-AG-D-ZK-KD | E03 | 3.1 | 31 | 7.21 | N | BZ | OTS | - | 11.25 | E03-T02-001-31 | LF | L | SG | 1 | - | 1265Rau0000000005 | 1263Mak0812546291 | 2.52521 | 150 | 100 | no | EI2 30 | 0 | yes | SA | AllplanAttributes (SMT) - Text2: -; Text4: Stahl-Glas-Tür; Pset_DoorCommon - HandicapAccessible: no; FireExit: no
SMT | H2 Ebene 0 | 2.7 | 1.50003 | TI-1F-UZ-D | E00 | 3.0 | 2 | 9.63 | - | - | - | EMF | 0 | TA-1FL-D-E00-010 | - | - | - | 0 | S | 1115Rau0000005163 | 1105Mak0000032937 | 2.45286 | 200 | 0 | yes | 0 | 1 | no | RC 2 | - | SVP | 0,35 | U23 | 32 | T_Typ9 | AllplanAttributes (SMT) - Text3: Handauslösetaster; ash T_Steuerung (BG): A; ash T_Steuerung (BS): E
SMT | H2 Ebene 0 | 3.1 | 1.50003 | TA-1F-AG-D | E00 | 3.1 | 7 | 7.21 | - | - | OTS | - | 0 | TA-1FL-D-E00-005 | - | - | - | 0 | S | 1115Rau0000005075 | 1105Mak0000034995 | 3.13163 | 200 | 100 | yes | 0 | 1.4 | no | RC 2 | - | SVP | 0,35 | U23 | 32 | T_Typ5 | AllplanAttributes (SMT) - ash D_Detailverweis: Typ5; ash D_Plannummer: D1753
SMT | H2 Ebene 0 | 3.1 | 1.50003 | TA-1F-AG-D-O | E00 | 3.1 | 12 | 7.21 | - | - | OTS | - | 0 | TA-1FL-D-E00-007 | - | - | - | 0 | S | 1115Rau0000005078 | 1105Mak0000034336 | 3.13163 | 200 | 100 | yes | 0 | 1 | no | RC 2 | - | SVP | 0,35 | U23 | 32 | T_Typ5

# IfcDoor: SMT (2)
Type - PredefinedType: DOOR; OperationType: SINGLE_SWING_RIGHT; ParameterTakesPrecedence: no
Type - IfcDoorLiningProperties - LiningDepth: 0.08 m; LiningThickness: 0.05 m
OverallWidth: 1.56 m; Material: TI-1F-AG-D-O
AllplanAttributes (SMT) - Gewerk: Zimmer- und Holzbauarbeiten; V6: 0 m; V7: 0 m; V8: 0 m; V9: 0; Ortscode_Geschoßbezeichnung: E00; Programmversion: 3.1; Objektname: Türmakro; Text1: 43; Text2: X; Text4: Stahl-Glas-Tür; Bezeichnung: SMT; Material: TI-1F-AG-D-O; Plugin_Bezeichnung: MainObject; Plugin_Objektname: SmartPartCompressed; Glasanteil_berücksichtigen: 100; Version: 7.21; ash T_Sichtschutz: -; ash R_Verweis Wandansicht: -; ash T_Zulage Schachttür: no; ash T_Dichtschließend: no; ash T_Panik: N; ash T_Zarge_Typ: BZ; ash T_Türschließer: OTS; ash T_Gewerk Los: -; ash T_Erforderl. Durchgangsbreite: 0 m; ash T_Türblatt sichtbar 2D: ja; ash T_Zusatzfunktion Panikschloss: -; ash T_Fluchtwegsicherung: FWS; ash T_Standflügel-Betätigung: -; ash T_Zusatzfunktion Türschließer: -; ash T_Türschließer-Montage: -; ash T_Feststellanlage (FSA): -; ash T_Zusätzliche Rauchmelder: -; ash T_Zusätzl. Anschluss an BMA: -; ash T_Impulsgeber: -; ash T_Sicherheits-Sensorleisten: -; ash T_Anschl. an Zuttrittskontrolle: ZK; ash T_Anschl. an Einbruchmeld.anl.: -; ash T_Klemmschutz: -; ash T_LV-Positions-Nr.: -; ash T_Plan-Nr.: -; ash T_Sonstiges, Bemerkungen: -; OKFF: 0; ash T_Bodentürstopper: -; ash T_nicht abschließbar: no; ash T_Material Seitenteil: -; ash T_Strahlenschutz: 0.000000; ash T_Kantengeometrie: -; ash T_Kantenmaterial: -; ash T_Blatt_Oberfläche: L; ash T_Erford. Durgangshöhe: 0 m; ash T_Laserschutz: -; ash T_Rammschutz: SB; ash T_Fluchtwegrichtung: A; ash T_Anschlag Gangflügel: -; ash T_Bodendichtung: -; ash T_Lüftungsgitter: 0 m2; ash T_Feuchtebeständigkeit: -; ash T_E_Öffner: TÖ + FTÖ; ash T_Automatik_Antrieb: -; ash T_Blatt_Material: S; ash T_Schlossfunktion: E; ash T_Schliesszylinder: PZ(v); ash T_Beschlag: KD; ash T_Glasausschnitt: -; ash T_Sonder_Wandmaterial: -; ash T_Anz_Reedkontakte: 0; ash T_Anz_Riegelkontakte: 1; ash T_Schallschutz: -; ash T_Zarge_Material: -; ash T_Bodeneinstand: -; ash T_Raum zugehörigkeit: BS; ash T_Blatt_Farbe: -; ash T_Steuerung (BG): E, H; ash T_Steuerung (BS): E, H; Positionsnummer_Text: S68; Attributset-Objekt: Door; P_ID: 1115Rau0000005069; Abrechnungsart: St
AllplanQuantities - HeightWindowSillOutside: 0; HeightWindowSillInside: 0; OffsetOpeningBottom: 200; OffsetOpeningTop: 0; OffsetOpeningLeft: 0; OffsetOpeningRight: 0; DeductionOpeningBottom: 100; DeductionOpeningLeft: 50; DeductionOpeningRight: 50; DeductionOpeningTop: 50
Pset_DoorCommon - Status: NEW; IsExternal: no; FireRating: EI2 30; ThermalTransmittance: 0 W/K/m2; HandicapAccessible: no; SmokeStop: yes; SelfClosing: yes; FireExit: yes
Name | In | OverallHeight (m) | ash T_Tür-Nr. | Allright_Bauteil_ID | GlassSurface
SMT | H2 Ebene +1 | 2.53 | E01-T02-001-43 | 1163Mak0814486652 | 2.4072 | Pset_DoorCommon - SecurityRating: SA
SMT | H2 Ebene 0 | 2.58 | E00-T02-001-43 | 1113Mak0814025282 | 2.4662

# IfcDoor: SMT
In: H2 Ebene 0
Type - PredefinedType: DOOR; OperationType: SINGLE_SWING_RIGHT; ParameterTakesPrecedence: no
Type - IfcDoorLiningProperties - LiningDepth: 0.08 m; LiningThickness: 0.07 m
OverallHeight: 2.6 m; OverallWidth: 1.50003 m; Material: TA-1F-AG-D
AllplanAttributes (SMT) - Gewerk: Metallbau-, Schlosserarbeiten; V6: 0 m; V7: 0 m; V8: 0 m; V9: 0; Ortscode_Geschoßbezeichnung: E00; Programmversion: 3.1; Objektname: Türmakro; Text1: 3; Bezeichnung: SMT; Material: TA-1F-AG-D; Plugin_Bezeichnung: MainObject; Plugin_Objektname: SmartPartCompressed; Glasanteil_berücksichtigen: 100; Version: 7.21; ash T_Sichtschutz: -; ash T_Zulage Schachttür: no; ash T_Dichtschließend: no; ash T_Panik: -; ash T_Zarge_Typ: -; ash T_Türschließer: OTS; ash T_Gewerk Los: -; ash T_Erforderl. Durchgangsbreite: 0 m; ash T_Türblatt sichtbar 2D: ja; ash T_Zusatzfunktion Panikschloss: -; ash T_Fluchtwegsicherung: -; ash T_Standflügel-Betätigung: -; ash T_Zusatzfunktion Türschließer: -; ash T_Türschließer-Montage: -; ash T_Feststellanlage (FSA): -; ash T_Zusätzliche Rauchmelder: -; ash T_Zusätzl. Anschluss an BMA: -; ash T_Impulsgeber: -; ash T_Sicherheits-Sensorleisten: -; ash T_Anschl. an Zuttrittskontrolle: -; ash T_Anschl. an Einbruchmeld.anl.: -; ash T_Klemmschutz: -; ash T_LV-Positions-Nr.: -; ash T_Plan-Nr.: -; ash T_Sonstiges, Bemerkungen: -; OKFF: 0; ash T_Bodentürstopper: -; ash T_nicht abschließbar: no; ash T_Türtyp Nr.: -; ash T_Material Seitenteil: -; ash T_Strahlenschutz: 0.000000; ash T_Tür-Nr.: TA-1FL-D-E00-011; ash T_Kantengeometrie: -; ash T_Kantenmaterial: -; ash T_Blatt_Oberfläche: -; ash T_Erford. Durgangshöhe: 0 m; ash T_Laserschutz: -; ash T_Rammschutz: -; ash T_Fluchtwegrichtung: -; ash T_Anschlag Gangflügel: -; ash T_Bodendichtung: -; ash T_Lüftungsgitter: 0 m2; ash T_Feuchtebeständigkeit: -; ash T_E_Öffner: -; ash T_Automatik_Antrieb: -; ash T_Sturz: -; ash T_Blatt_Material: -; ash T_Schlossfunktion: SVP; ash T_Schliesszylinder: PZ; ash T_Beschlag: KD; ash T_Material Oberlicht: -; ash T_Glasausschnitt: -; ash T_Sonder_Wandmaterial: -; ash T_Anz_Reedkontakte: 0; ash T_Anz_Riegelkontakte: 0; ash T_Schallschutz: -; ash T_Zarge_Material: S; ash T_Bodeneinstand: -; ash T_Raum zugehörigkeit: BS; ash T_Blatt_Farbe: -; ash D_Detailverweis: Typ9; ash D_Plannummer: D1756; g-Wert: 0,51; Positionsnummer_Text: U23; Attributset-Objekt: Door; P_ID: 1115Rau0000005069; Allright_Bauteil_ID: 1105Mak0000035990; Abrechnungsart: St
AllplanQuantities - GlassSurface: 2.80806; HeightWindowSillOutside: 0; HeightWindowSillInside: 0; OffsetOpeningBottom: 10; OffsetOpeningTop: 0; OffsetOpeningLeft: 0; OffsetOpeningRight: 0; DeductionOpeningBottom: 10; DeductionOpeningLeft: 70; DeductionOpeningRight: 70; DeductionOpeningTop: 70
Pset_DoorCommon - Status: NEW; IsExternal: yes; FireRating: 0; ThermalTransmittance: 1 W/K/m2; AcousticRating: 32; SmokeStop: no; SelfClosing: no; SecurityRating: RC 2; Reference: T_Typ9

# IfcDoor: SMT (5)
Type - PredefinedType: DOOR; OperationType: SINGLE_SWING_RIGHT; ParameterTakesPrecedence: no
Type - IfcDoorLiningProperties - LiningDepth: 0.105 m; LiningThickness: 0.04 m
AllplanAttributes (SMT) - V6: 0 m; V7: 0 m; V8: 0 m; V9: 0; Programmversion: 3.1; Objektname: Türmakro; Bezeichnung: SMT; Plugin_Bezeichnung: MainObject; Plugin_Objektname: SmartPartCompressed; Glasanteil_berücksichtigen: 100; Version: 7.21; ash T_Sichtschutz: -; ash R_Verweis Wandansicht: -; ash T_Zulage Schachttür: no; ash T_Panik: -; ash T_Zarge_Typ: UZ; ash T_Gewerk Los: -; ash T_Erforderl. Durchgangsbreite: 0 m; ash T_Türblatt sichtbar 2D: ja; ash T_Zusatzfunktion Panikschloss: -; ash T_Fluchtwegsicherung: -; ash T_Standflügel-Betätigung: -; ash T_Zusatzfunktion Türschließer: -; ash T_Türschließer-Montage: -; ash T_Feststellanlage (FSA): -; ash T_Zusätzliche Rauchmelder: -; ash T_Zusätzl. Anschluss an BMA: -; ash T_Impulsgeber: -; ash T_Sicherheits-Sensorleisten: -; ash T_Anschl. an Einbruchmeld.anl.: -; ash T_Klemmschutz: -; ash T_LV-Positions-Nr.: -; ash T_Plan-Nr.: -; ash T_Sonstiges, Bemerkungen: -; ash T_Bodentürstopper: -; ash T_nicht abschließbar: no; ash T_Material Seitenteil: -; ash T_Strahlenschutz: 0.000000; ash T_Kantengeometrie: 2F; ash T_Kantenmaterial: PU; ash T_Blatt_Oberfläche: HPL; ash T_Erford. Durgangshöhe: 0 m; ash T_Rammschutz: BL; ash T_Fluchtwegrichtung: -; ash T_Anschlag Gangflügel: -; ash T_Bodendichtung: -; ash T_Lüftungsgitter: 0 m2; ash T_E_Öffner: -; ash T_Automatik_Antrieb: -; ash T_Sturz: -; ash T_Blatt_Material: HO; ash T_Schlossfunktion: -; ash T_Beschlag: KD; ash T_Glasausschnitt: -; ash T_Sonder_Wandmaterial: -; ash T_Anz_Reedkontakte: 0; ash T_Anz_Riegelkontakte: 0; ash T_Schallschutz: -; ash T_Zarge_Material: ST; ash T_Bodeneinstand: -; ash T_Raum zugehörigkeit: BGS; ash T_Blatt_Farbe: -; Attributset-Objekt: Door; Abrechnungsart: St
AllplanQuantities - GlassSurface: 0; HeightWindowSillOutside: 0; HeightWindowSillInside: 0; OffsetOpeningTop: 0; OffsetOpeningLeft: 0; OffsetOpeningRight: 0; DeductionOpeningBottom: 100; DeductionOpeningLeft: 40; DeductionOpeningRight: 40; DeductionOpeningTop: 40
Pset_DoorCommon - Status: NEW; IsExternal: no; ThermalTransmittance: 0 W/K/m2; HandicapAccessible: no; FireExit: no
Name | In | OverallHeight (m) | OverallWidth (m) | Material = AllplanAttributes (SMT), Material | Gewerk | Ortscode_Geschoßbezeichnung | Text1 | ash T_Dichtschließend | ash T_Türschließer | OKFF | ash T_Tür-Nr. | ash T_Feuchtebeständigkeit | ash T_Schliesszylinder | Positionsnummer_Text | P_ID | Allright_Bauteil_ID | OffsetOpeningBottom | FireRating | SmokeStop = SelfClosing
SMT | H2 Ebene +1 | 2.41 | 1.135 | TI-1F-UZ-D-N | Zimmer- und Holzbauarbeiten | E01 | 121 | yes | - | 3.75 | E01-078-001-121 | N | Kn-PZ | U100 | 1165Rau0000004712 | 1163Mak0814620401 | 150 | - | no
SMT | H2 Ebene +1 | 2.41 | 1.01 | TI-1F-UZ-ZK | Metallbau-, Schlosserarbeiten | E01 | 130 | no | OTS | 3.75 | E01-081-001-130 | - | PZ | U100 | 1165Rau0000004725 | 1163Mak0812655395 | 150 | EI2 30 | yes
SMT | H2 Ebene +1 | 2.41 | 1.01 | TI-1F-UZ-ZK | Metallbau-, Schlosserarbeiten | E01 | 44 | no | OTS | 3.75 | E01-029-001-44 | - | PZ | U100 | 1165Rau0000004677 | 1163Mak0814418664 | 150 | EI2 30 | yes
SMT | H2 Ebene 0 | 2.46 | 1.01 | TI-1F-UZ-ZK | Metallbau-, Schlosserarbeiten | E00 | 130 | no | OTS | 0 | E00-081-001-130 | - | PZ | S68 | 1115Rau0000005072 | 1113Mak0812655395 | 200 | EI2 30 | yes
SMT | H2 Ebene 0 | 2.46 | 1.01 | TI-1F-UZ-ZK | Metallbau-, Schlosserarbeiten | E00 | 44 | no | OTS | 0 | E00-029-001-44 | - | PZ | S68 | 1115Rau0000005065 | 1113Mak0814166042 | 200 | EI2 30 | yes

# IfcDoor: SMT (84)
Type - PredefinedType: DOOR; OperationType: SINGLE_SWING_RIGHT; ParameterTakesPrecedence: no
Type - IfcDoorLiningProperties - LiningDepth: 0.155 m; LiningThickness: 0.04 m
AllplanAttributes (SMT) - Gewerk: Metallbau-, Schlosserarbeiten; V6: 0 m; V7: 0 m; V8: 0 m; V9: 0; Programmversion: 3.1; Objektname: Türmakro; Bezeichnung: SMT; Plugin_Bezeichnung: MainObject; Plugin_Objektname: SmartPartCompressed; Glasanteil_berücksichtigen: 100; Version: 7.21; ash T_Unterschnitt: 1; ash T_Sichtschutz: -; ash R_Verweis Wandansicht: -; ash T_Zulage Schachttür: no; ash T_Dichtschließend: no; ash T_Panik: -; ash T_Türschließer: -; ash T_Gewerk Los: -; ash T_Erforderl. Durchgangsbreite: 0 m; ash T_Türblatt sichtbar 2D: ja; ash T_Zusatzfunktion Panikschloss: -; ash T_Fluchtwegsicherung: -; ash T_Standflügel-Betätigung: -; ash T_Zusatzfunktion Türschließer: -; ash T_Türschließer-Montage: -; ash T_Feststellanlage (FSA): -; ash T_Zusätzliche Rauchmelder: -; ash T_Zusätzl. Anschluss an BMA: -; ash T_Impulsgeber: -; ash T_Sicherheits-Sensorleisten: -; ash T_Anschl. an Einbruchmeld.anl.: -; ash T_Klemmschutz: -; ash T_LV-Positions-Nr.: -; ash T_Plan-Nr.: -; ash T_Sonstiges, Bemerkungen: -; ash T_Bodentürstopper: -; ash T_nicht abschließbar: no; ash T_Material Seitenteil: -; ash T_Kantengeometrie: 2F; ash T_Kantenmaterial: PU; ash T_Blatt_Oberfläche: HPL; ash T_Erford. Durgangshöhe: 0 m; ash T_Rammschutz: BL; ash T_Fluchtwegrichtung: -; ash T_Bodendichtung: -; ash T_Lüftungsgitter: 0 m2; ash T_E_Öffner: -; ash T_Automatik_Antrieb: -; ash T_Blatt_Material: HO; ash T_Schlossfunktion: -; ash T_Schliesszylinder: WC; ash T_Beschlag: DD; ash T_Glasausschnitt: -; ash T_Sonder_Wandmaterial: -; ash T_Anz_Reedkontakte: 0; ash T_Anz_Riegelkontakte: 0; ash T_Schallschutz: -; ash T_Bodeneinstand: -; ash T_Raum zugehörigkeit: BGS; ash T_Blatt_Farbe: -; Attributset-Objekt: Door; Abrechnungsart: St
AllplanAttributes (TGR 1.6) - Codetext: Typ; V6: 0 m; V7: 0 m; V8: 0 m; V9: 0; Programmversion: 3.1; Objektname: TGR-Makro; Text1: PlanNo.; Bezeichnung: TGR 1.6; Plugin_Bezeichnung: MainObject; Plugin_Objektname: SmartPartCompressed; Version: 1.6; Abrechnungsart: St
AllplanQuantities - GlassSurface: 0; HeightWindowSillOutside: 0; HeightWindowSillInside: 0; OffsetOpeningTop: 0; OffsetOpeningLeft: 0; OffsetOpeningRight: 0; DeductionOpeningBottom: 100; DeductionOpeningLeft: 40; DeductionOpeningRight: 40; DeductionOpeningTop: 40
Pset_DoorCommon - Status: NEW; IsExternal: no; ThermalTransmittance: 0 W/K/m2; SmokeStop: no; SelfClosing: no; FireExit: no
Name | In | OverallHeight (m) | OverallWidth (m) | Material = AllplanAttributes (SMT), Material | AllplanAttributes (SMT), Ortscode_Geschoßbezeichnung | Text1 | ash T_Zarge_Typ | AllplanAttributes (SMT), OKFF | ash T_Tür-Nr. | ash T_Feuchtebeständigkeit | ash T_Sturz | ash T_Zarge_Material | P_ID | AllplanAttributes (SMT), Allright_Bauteil_ID | Gesamtlänge | AllplanAttributes (TGR 1.6), OKFF | ash T_Türprofilnummer | AllplanAttributes (TGR 1.6), Allright_Bauteil_ID | OffsetOpeningBottom | HandicapAccessible | ash T_Strahlenschutz | ash T_Anschlag Gangflügel | AllplanAttributes (SMT), Positionsnummer_Text = AllplanAttributes (TGR 1.6), Positionsnummer_Text
SMT | H2 Ebene +2 | 2.41 | 1.01 | TI-1F-UZ-D | E02 | 36 | UZ | 7.5 | E02-025a-001-36 | N | - | ST | 1216Rau0000046211 | 1213Mak0813004654 | 8.11 | 7.5 | 5 | 1213Mak0813223773 | 150 | no | AllplanAttributes (TGR 1.6) - Ortscode_Geschoßbezeichnung: E02
SMT | H2 Ebene +2 | 2.41 | 1.01 | TI-1F-UZ-D | E02 | 33 | UZ | 7.5 | E02-024a-001-33 | N | - | ST | 1216Rau0000046237 | 1213Mak0813004649 | 8.11 | 7.5 | 5 | 1213Mak0813223776 | 150 | no | AllplanAttributes (TGR 1.6) - Ortscode_Geschoßbezeichnung: E02
SMT | H2 Ebene +2 | 2.41 | 1.135 | TI-1F-UZ-D | E02 | 32 | UZ | 7.5 | E02-023a-001-32 | N | - | ST | 1216Rau0000046263 | 1213Mak0813004674 | 8.235 | 7.5 | 3 | 1213Mak0813223794 | 150 | no | AllplanAttributes (TGR 1.6) - Ortscode_Geschoßbezeichnung: E02
SMT | H2 Ebene +2 | 2.41 | 1.01 | TI-1F-UZ-D | E02 | 29 | UZ | 7.5 | E02-022a-001-29 | N | - | ST | 1216Rau0000046301 | 1213Mak0813004659 | 8.11 | 7.5 | 5 | 1213Mak0813223797 | 150 | no | AllplanAttributes (TGR 1.6) - Ortscode_Geschoßbezeichnung: E02
SMT | H2 Ebene +2 | 2.41 | 1.01 | TI-1F-UZ-D | E02 | 28 | UZ | 7.5 | E02-021a-001-28 | N | - | ST | 1216Rau0000046315 | 1213Mak0813004664 | 8.11 | 7.5 | 5 | 1213Mak0813223800 | 150 | no | AllplanAttributes (TGR 1.6) - Ortscode_Geschoßbezeichnung: E02
SMT | H2 Ebene +2 | 2.41 | 1.01 | TI-1F-UZ-D | E02 | 25 | UZ | 7.5 | E02-020a-001-25 | N | - | ST | 1216Rau0000046353 | 1213Mak0813004669 | 8.11 | 7.5 | 5 | 1213Mak0813223803 | 150 | no | AllplanAttributes (TGR 1.6) - Ortscode_Geschoßbezeichnung: E02
SMT | H2 Ebene +2 | 2.41 | 1.135 | TI-1F-UZ-D | E02 | 106 | UZ | 7.5 | E02-068a-001-106 | N | - | ST | 1216Rau0000047273 | 1213Mak0813004467 | 8.235 | 7.5 | 3 | 1213Mak0813223991 | 150 | no | AllplanAttributes (TGR 1.6) - Ortscode_Geschoßbezeichnung: E02
SMT | H2 Ebene +2 | 2.41 | 1.01 | TI-1F-UZ-D | E02 | 141 | UZ | 7.5 | E02-091a-001-141 | N | - | ST | 1216Rau0000047039 | 1213Mak0813004309 | 8.11 | 7.5 | 5 | 1213Mak0813223917 | 150 | no | AllplanAttributes (TGR 1.6) - Ortscode_Geschoßbezeichnung: E02
SMT | H2 Ebene +2 | 2.41 | 1.01 | TI-1F-UZ-D | E02 | 140 | UZ | 7.5 | E02-090a-001-140 | N | - | ST | 1216Rau0000047077 | 1213Mak0813004314 | 8.11 | 7.5 | 5 | 1213Mak0813223920 | 150 | no | AllplanAttributes (TGR 1.6) - Ortscode_Geschoßbezeichnung: E02
SMT | H2 Ebene +2 | 2.41 | 1.01 | TI-1F-UZ-D | E02 | 149 | UZ | 7.5 | E02-095a-001-149 | N | - | ST | 1216Rau0000046909 | 1213Mak0813004319 | 8.11 | 7.5 | 5 | 1213Mak0813223905 | 150 | no | AllplanAttributes (TGR 1.6) - Ortscode_Geschoßbezeichnung: E02
SMT | H2 Ebene +2 | 2.41 | 1.01 | TI-1F-UZ-D | E02 | 145 | UZ | 7.5 | E02-093a-001-145 | N | - | ST | 1216Rau0000046987 | 1213Mak0813004304 | 8.11 | 7.5 | 5 | 1213Mak0813223911 | 150 | no | AllplanAttributes (TGR 1.6) - Ortscode_Geschoßbezeichnung: E02
SMT | H2 Ebene +2 | 2.41 | 1.135 | TI-1F-UZ-D | E02 | 144 | UZ | 7.5 | E02-092a-001-144 | N | - | ST | 1216Rau0000047025 | 1213Mak0813004324 | 8.235 | 7.5 | 3 | 1213Mak0813223914 | 150 | no | AllplanAttributes (TGR 1.6) - Ortscode_Geschoßbezeichnung: E02
SMT | H2 Ebene +2 | 2.41 | 1.01 | TI-1F-UZ-D | E02 | 148 | UZ | 7.5 | E02-094a-001-148 | N | - | ST | 1216Rau0000046947 | 1213Mak0813004299 | 8.11 | 7.5 | 5 | 1213Mak0813223908 | 150 | no | AllplanAttributes (TGR 1.6) - Ortscode_Geschoßbezeichnung: E02
SMT | H2 Ebene +2 | 2.41 | 1.01 | TI-1F-UZ-D | E02 | 117 | UZ | 7.5 | E02-073a-001-117 | N | - | ST | 1216Rau0000047391 | 1213Mak0813004452 | 8.11 | 7.5 | 5 | 1213Mak0813223976 | 150 | no | AllplanAttributes (TGR 1.6) - Ortscode_Geschoßbezeichnung: E02
SMT | H2 Ebene +2 | 2.41 | 1.01 | TI-1F-UZ-D | E02 | 118 | UZ | 7.5 | E02-074a-001-118 | - | - | ST | 1216Rau0000047417 | 1213Mak0813004457 | 8.11 | 7.5 | 5 | 1213Mak0813223973 | 150 | no | AllplanAttributes (TGR 1.6) - Ortscode_Geschoßbezeichnung: E02
SMT | H2 Ebene +2 | 2.41 | 1.01 | TI-1F-UZ-D | E02 | 109 | UZ | 7.5 | E02-069a-001-109 | N | - | ST | 1216Rau0000047287 | 1213Mak0813004437 | 8.11 | 7.5 | 5 | 1213Mak0813223988 | 150 | no | AllplanAttributes (TGR 1.6) - Ortscode_Geschoßbezeichnung: E02
SMT | H2 Ebene +2 | 2.41 | 1.01 | TI-1F-UZ-D | E02 | 113 | UZ | 7.5 | E02-071a-001-113 | N | - | ST | 1216Rau0000047339 | 1213Mak0813004447 | 8.11 | 7.5 | 5 | 1213Mak0813223982 | 150 | no | AllplanAttributes (TGR 1.6) - Ortscode_Geschoßbezeichnung: E02
SMT | H2 Ebene +2 | 2.41 | 1.135 | TI-1F-UZ-D | E02 | 114 | UZ | 7.5 | E02-072a-001-114 | N | - | ST | 1216Rau0000047365 | 1213Mak0813004462 | 8.235 | 7.5 | 3 | 1213Mak0813223979 | 150 | no | AllplanAttributes (TGR 1.6) - Ortscode_Geschoßbezeichnung: E02
SMT | H2 Ebene +2 | 2.41 | 1.01 | TI-1F-UZ-D | E02 | 110 | UZ | 7.5 | E02-070a-001-110 | N | - | ST | 1216Rau0000047313 | 1213Mak0813004442 | 8.11 | 7.5 | 5 | 1213Mak0813223985 | 150 | no | AllplanAttributes (TGR 1.6) - Ortscode_Geschoßbezeichnung: E02
SMT | H2 Ebene +2 | 4.9101 | 1.01 | TI-1F-UZ-D | E02 | 24 | UZ | 7.5 | E02-019a-001-24 | N | - | ST | 1216Rau0000046367 | 1213Mak0813004644 | 8.11 | 7.5 | 5 | 1213Mak0813223806 | 150 | no | 0.000000 | - | AllplanAttributes (TGR 1.6) - Ortscode_Geschoßbezeichnung: E02; AllplanAttributes (SMT) - ash T_Laserschutz: -
SMT | H2 Ebene +2 | 2.41 | 1.01 | TI-1F-UZ-D | E02 | 56 | UZ | 7.5 | E02-041a-001-56 | N | - | ST | 1216Rau0812778629 | 1213Mak0813004534 | 8.11 | 7.5 | 5 | 1213Mak0813223647 | 150 | no | AllplanAttributes (TGR 1.6) - Ortscode_Geschoßbezeichnung: E02
SMT | H2 Ebene +2 | 2.41 | 1.01 | TI-1F-UZ-D | E02 | 57 | UZ | 7.5 | E02-042a-001-57 | N | - | ST | 1216Rau0000045891 | 1213Mak0813004539 | 8.11 | 7.5 | 5 | 1213Mak0813223662 | 150 | no | AllplanAttributes (TGR 1.6) - Ortscode_Geschoßbezeichnung: E02
SMT | H2 Ebene +2 | 2.41 | 1.135 | TI-1F-UZ-D | E02 | 60 | UZ | 7.5 | E02-043a-001-60 | N | - | ST | 1216Rau0000045905 | 1213Mak0813004544 | 8.235 | 7.5 | 3 | 1213Mak0813223679 | 150 | no | AllplanAttributes (TGR 1.6) - Ortscode_Geschoßbezeichnung: E02
SMT | H2 Ebene +2 | 2.41 | 1.01 | TI-1F-UZ-D | E02 | 61 | UZ | 7.5 | E02-044a-001-61 | N | - | ST | 1216Rau0000045943 | 1213Mak0813004529 | 8.11 | 7.5 | 5 | 1213Mak0813223682 | 150 | no | AllplanAttributes (TGR 1.6) - Ortscode_Geschoßbezeichnung: E02
SMT | H2 Ebene +2 | 2.41 | 1.01 | TI-1F-UZ-D | E02 | 64 | UZ | 7.5 | E02-045a-001-64 | N | - | ST | 1216Rau0000045957 | 1213Mak0813004524 | 8.11 | 7.5 | 5 | 1213Mak0813223685 | 150 | no | AllplanAttributes (TGR 1.6) - Ortscode_Geschoßbezeichnung: E02
SMT | H2 Ebene +2 | 2.41 | 1.01 | TI-1F-UZ-D | E02 | 65 | UZ | 7.5 | E02-046a-001-65 | N | - | ST | 1216Rau0000045995 | 1213Mak0813004519 | 8.11 | 7.5 | 5 | 1213Mak0813223688 | 150 | no | AllplanAttributes (TGR 1.6) - Ortscode_Geschoßbezeichnung: E02
SMT | H2 Ebene +2 | 2.41 | 1.135 | TI-1F-UZ-D | E02 | 68 | UZ | 7.5 | E02-047a-001-68 | N | - | ST | 1216Rau0000046009 | 1213Mak0813004549 | 8.235 | 7.5 | 3 | 1213Mak0813223720 | 150 | no | AllplanAttributes (TGR 1.6) - Ortscode_Geschoßbezeichnung: E02
SMT | H2 Ebene +2 | 2.41 | 1.01 | TI-1F-UZ-D | E02 | 152 | UZ | 7.5 | E02-096a-001-152 | N | - | ST | 1216Rau0000046883 | 1213Mak0813004294 | 8.11 | 7.5 | 5 | 1213Mak0813223902 | 150 | no | AllplanAttributes (TGR 1.6) - Ortscode_Geschoßbezeichnung: E02; AllplanAttributes (SMT) - ash T_Anschl. an Zuttrittskontrolle: -
SMT | H2 Ebene +1 | 2.41 | 1.01 | TI-1F-UZ-D-N | E01 | 33 | UZ | 3.75 | E01-024a-001-33 | N | - | ST | 1166Rau0000033359 | 1163Mak0812445990 | 8.11 |  | 5 | 1163Mak0814151729 | 150 | no | 0.000000 | - | U100 | AllplanAttributes (SMT) - ash T_Laserschutz: -; ash T_Anschl. an Zuttrittskontrolle: -; Pset_DoorCommon - SecurityRating: SA
SMT | H2 Ebene +1 | 2.41 | 1.135 | TI-1F-UZ-D-N | E01 | 32 | UZ | 3.75 | E01-023a-001-32 | N | - | ST | 1166Rau0000033346 | 1163Mak0812445982 | 8.235 |  | 3 | 1163Mak0814151142 | 150 | no | 0.000000 | - | U100 | AllplanAttributes (SMT) - ash T_Laserschutz: -; ash T_Anschl. an Zuttrittskontrolle: -; Pset_DoorCommon - SecurityRating: SA
SMT | H2 Ebene +1 | 2.41 | 1.01 | TI-1F-UZ-D-N | E01 | 29 | UZ | 3.75 | E01-022a-001-29 | N | - | ST | 1166Rau0000033333 | 1163Mak0812445978 | 8.11 |  | 5 | 1163Mak0814151732 | 150 | no | 0.000000 | - | U100 | AllplanAttributes (SMT) - ash T_Laserschutz: -; ash T_Anschl. an Zuttrittskontrolle: -; Pset_DoorCommon - SecurityRating: SA
SMT | H2 Ebene +1 | 2.41 | 1.01 | TI-1F-UZ-D-N | E01 | 28 | UZ | 3.75 | E01-021a-001-28 | N | - | ST | 1166Rau0000033320 | 1163Mak0812445974 | 8.11 |  | 5 | 1163Mak0814151763 | 150 | no | 0.000000 | - | U100 | AllplanAttributes (SMT) - ash T_Laserschutz: -; ash T_Anschl. an Zuttrittskontrolle: -; Pset_DoorCommon - SecurityRating: SA
SMT | H2 Ebene +1 | 2.41 | 1.01 | TI-1F-UZ-D-N | E01 | 25 | UZ | 3.75 | E01-020a-001-25 | N | - | ST | 1166Rau0000033307 | 1163Mak0812445970 | 8.11 |  | 5 | 1163Mak0814151766 | 150 | no | 0.000000 | - | U100 | AllplanAttributes (SMT) - ash T_Laserschutz: -; ash T_Anschl. an Zuttrittskontrolle: -; Pset_DoorCommon - SecurityRating: SA
SMT | H2 Ebene +1 | 2.41 | 1.135 | TI-1F-UZ-D-N | E01 | 106 | UZ | 3.75 | E01-068a-001-106 | N | - | ST | 1166Rau0000033862 | 1163Mak0812440141 | 8.235 |  | 3 | 1163Mak0814150938 | 150 | no | 0.000000 | - | U100 | AllplanAttributes (SMT) - ash T_Laserschutz: -; ash T_Anschl. an Zuttrittskontrolle: -; Pset_DoorCommon - SecurityRating: SA
SMT | H2 Ebene +1 | 2.41 | 1.01 | TI-1F-UZ-D-N | E01 | 141 | UZ | 3.75 | E01-091a-001-141 | N | - | ST | 1166Rau0000034414 | 1163Mak0812436848 | 8.11 |  | 5 | 1163Mak0814151814 | 150 | no | 0.000000 | - | U100 | AllplanAttributes (SMT) - ash T_Laserschutz: -; ash T_Anschl. an Zuttrittskontrolle: -; Pset_DoorCommon - SecurityRating: SA
SMT | H2 Ebene +1 | 2.41 | 1.01 | TI-1F-UZ-D-N | E01 | 140 | UZ | 3.75 | E01-090a-001-140 | N | - | ST | 1166Rau0000034401 | 1163Mak0812436844 | 8.11 |  | 5 | 1163Mak0814151817 | 150 | no | 0.000000 | - | U100 | AllplanAttributes (SMT) - ash T_Laserschutz: -; ash T_Anschl. an Zuttrittskontrolle: -; Pset_DoorCommon - SecurityRating: SA
SMT | H2 Ebene +1 | 2.41 | 1.01 | TI-1F-UZ-D-N | E01 | 149 | UZ | 3.75 | E01-095a-001-149 | N | - | ST | 1166Rau0000034521 | 1163Mak0812436840 | 8.11 |  | 5 | 1163Mak0814151805 | 150 | no | 0.000000 | - | U100 | AllplanAttributes (SMT) - ash T_Laserschutz: -; ash T_Anschl. an Zuttrittskontrolle: -; Pset_DoorCommon - SecurityRating: SA
SMT | H2 Ebene +1 | 2.41 | 1.01 | TI-1F-UZ-D-N | E01 | 145 | UZ | 3.75 | E01-093a-001-145 | N | - | ST | 1166Rau0000034440 | 1163Mak0812436856 | 8.11 |  | 5 | 1163Mak0814151811 | 150 | no | 0.000000 | - | U100 | AllplanAttributes (SMT) - ash T_Laserschutz: -; ash T_Anschl. an Zuttrittskontrolle: -; Pset_DoorCommon - SecurityRating: SA
SMT | H2 Ebene +1 | 2.41 | 1.135 | TI-1F-UZ-D-N | E01 | 144 | UZ | 3.75 | E01-092a-001-144 | N | - | ST | 1166Rau0000034427 | 1163Mak0812436852 | 8.235 |  | 3 | 1163Mak0814151228 | 150 | no | 0.000000 | - | U100 | AllplanAttributes (SMT) - ash T_Laserschutz: -; ash T_Anschl. an Zuttrittskontrolle: -; Pset_DoorCommon - SecurityRating: SA
SMT | H2 Ebene +1 | 2.41 | 1.01 | TI-1F-UZ-D-N | E01 | 148 | UZ | 3.75 | E01-094a-001-148 | N | - | ST | 1166Rau0000034497 | 1163Mak0812436860 | 8.11 |  | 5 | 1163Mak0814151808 | 150 | no | 0.000000 | - | U100 | AllplanAttributes (SMT) - ash T_Laserschutz: -; ash T_Anschl. an Zuttrittskontrolle: -; Pset_DoorCommon - SecurityRating: SA
SMT | H2 Ebene +1 | 2.41 | 1.01 | TI-1F-UZ-D-N | E01 | 36 | UZ | 3.75 | E01-025a-001-36 | N | - | ST | 1166Rau0000033372 | 1163Mak0812445986 | 8.11 |  | 5 | 1163Mak0814151726 | 150 | no | 0.000000 | - | U100 | AllplanAttributes (SMT) - ash T_Laserschutz: -; ash T_Anschl. an Zuttrittskontrolle: -; Pset_DoorCommon - SecurityRating: SA
SMT | H2 Ebene +1 | 2.41 | 1.01 | TI-1F-UZ-D-N | E01 | 117 | UZ | 3.75 | E01-073a-001-117 | N | - | ST | 1166Rau0000033927 | 1163Mak0812436864 | 8.11 |  | 5 | 1163Mak0814151877 | 150 | no | 0.000000 | - | U100 | AllplanAttributes (SMT) - ash T_Laserschutz: -; ash T_Anschl. an Zuttrittskontrolle: -; Pset_DoorCommon - SecurityRating: SA
SMT | H2 Ebene +1 | 2.41 | 1.01 | TI-1F-UZ-D-N | E01 | 118 | UZ | 3.75 | E01-074a-001-118 | - | - | ST | 1166Rau0000033940 | 1163Mak0812436868 | 8.11 |  | 5 | 1163Mak0814151880 | 150 | no | 0.000000 | - | U100 | AllplanAttributes (SMT) - ash T_Laserschutz: -; ash T_Anschl. an Zuttrittskontrolle: -; Pset_DoorCommon - SecurityRating: SA
SMT | H2 Ebene +1 | 2.41 | 1.01 | TI-1F-UZ-D-N | E01 | 109 | UZ | 3.75 | E01-069a-001-109 | N | - | ST | 1166Rau0000033875 | 1163Mak0812436872 | 8.11 |  | 5 | 1163Mak0814151868 | 150 | no | 0.000000 | - | U100 | AllplanAttributes (SMT) - ash T_Laserschutz: -; ash T_Anschl. an Zuttrittskontrolle: -; Pset_DoorCommon - SecurityRating: SA
SMT | H2 Ebene +1 | 2.41 | 1.01 | TI-1F-UZ-D-N | E01 | 113 | UZ | 3.75 | E01-071a-001-113 | N | - | ST | 1166Rau0000033901 | 1163Mak0812436884 | 8.11 |  | 5 | 1163Mak0814151874 | 150 | no | 0.000000 | - | U100 | AllplanAttributes (SMT) - ash T_Laserschutz: -; ash T_Anschl. an Zuttrittskontrolle: -; Pset_DoorCommon - SecurityRating: SA
SMT | H2 Ebene +1 | 2.41 | 1.135 | TI-1F-UZ-D-N | E01 | 114 | UZ | 3.75 | E01-072a-001-114 | N | - | ST | 1166Rau0000033914 | 1163Mak0812436880 | 8.235 |  | 3 | 1163Mak0814151234 | 150 | no | 0.000000 | - | U100 | AllplanAttributes (SMT) - ash T_Laserschutz: -; ash T_Anschl. an Zuttrittskontrolle: -; Pset_DoorCommon - SecurityRating: SA
SMT | H2 Ebene +1 | 2.41 | 1.01 | TI-1F-UZ-D-N | E01 | 110 | UZ | 3.75 | E01-070a-001-110 | N | - | ST | 1166Rau0000033888 | 1163Mak0812436876 | 8.11 |  | 5 | 1163Mak0814151871 | 150 | no | 0.000000 | - | U100 | AllplanAttributes (SMT) - ash T_Laserschutz: -; ash T_Anschl. an Zuttrittskontrolle: -; Pset_DoorCommon - SecurityRating: SA
SMT | H2 Ebene +1 | 2.41 | 1.01 | TI-1F-UZ-D-N | E01 | 24 | UZ | 3.75 | E01-019a-001-24 | N | - | ST | 1166Rau0000033294 | 1163Mak0812446733 | 8.11 |  | 5 | 1163Mak0814151769 | 150 | no | 0.000000 | - | U100 | AllplanAttributes (SMT) - ash T_Laserschutz: -; ash T_Anschl. an Zuttrittskontrolle: -; Pset_DoorCommon - SecurityRating: SA
SMT | H2 Ebene +1 | 2.41 | 1.135 | TI-1F-UZ-D-N | E01 | 60 | UZ | 3.75 | E01-043a-001-60 | N | - | ST | 1166Rau0000033573 | 1163Mak0812441169 | 8.235 |  | 3 | 1163Mak0814150958 | 150 | no | 0.000000 | - | U100 | AllplanAttributes (SMT) - ash T_Laserschutz: -; ash T_Anschl. an Zuttrittskontrolle: -; Pset_DoorCommon - SecurityRating: SA
SMT | H2 Ebene +1 | 2.41 | 1.01 | TI-1F-UZ-D-N | E01 | 61 | UZ | 3.75 | E01-044a-001-61 | N | - | ST | 1166Rau0000033586 | 1163Mak0812441279 | 8.11 |  | 5 | 1163Mak0814151699 | 150 | no | 0.000000 | - | U100 | AllplanAttributes (SMT) - ash T_Laserschutz: -; ash T_Anschl. an Zuttrittskontrolle: -; Pset_DoorCommon - SecurityRating: SA
SMT | H2 Ebene +1 | 2.41 | 1.01 | TI-1F-UZ-D-N | E01 | 64 | UZ | 3.75 | E01-045a-001-64 | N | - | ST | 1166Rau0000033599 | 1163Mak0812441389 | 8.11 |  | 5 | 1163Mak0814151702 | 150 | no | 0.000000 | - | U100 | AllplanAttributes (SMT) - ash T_Laserschutz: -; ash T_Anschl. an Zuttrittskontrolle: -; Pset_DoorCommon - SecurityRating: SA
SMT | H2 Ebene +1 | 2.41 | 1.01 | TI-1F-UZ-D-N | E01 | 65 | UZ | 3.75 | E01-046a-001-65 | N | - | ST | 1166Rau0000033612 | 1163Mak0812441499 | 8.11 |  | 5 | 1163Mak0814151705 | 150 | no | 0.000000 | - | U100 | AllplanAttributes (SMT) - ash T_Laserschutz: -; ash T_Anschl. an Zuttrittskontrolle: -; Pset_DoorCommon - SecurityRating: SA
SMT | H2 Ebene +1 | 2.41 | 1.135 | TI-1F-UZ-D-N | E01 | 68 | UZ | 3.75 | E01-047a-001-68 | N | - | ST | 1166Rau0000033625 | 1163Mak0812441812 | 8.235 |  | 3 | 1163Mak0814150955 | 150 | no | 0.000000 | - | U100 | AllplanAttributes (SMT) - ash T_Laserschutz: -; ash T_Anschl. an Zuttrittskontrolle: -; Pset_DoorCommon - SecurityRating: SA
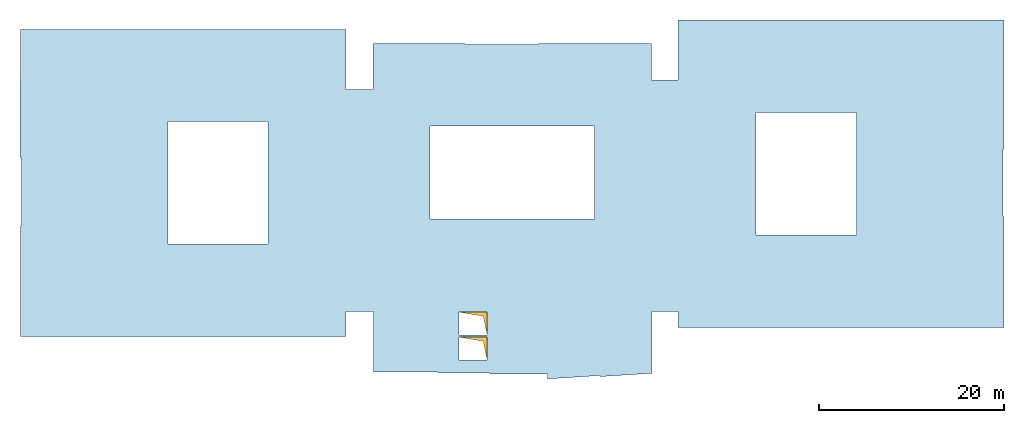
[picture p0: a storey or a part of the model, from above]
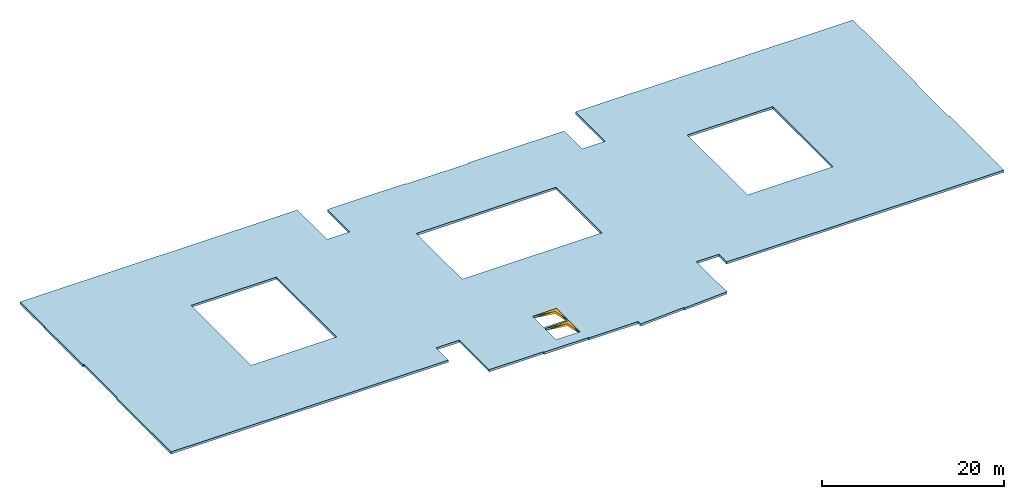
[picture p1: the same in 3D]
Properties of the parts of a building model (IFC4), part 26 of 80

# IfcDoor: SMT (84)
Name | In | OverallHeight (m) | OverallWidth (m) | Material = AllplanAttributes (SMT), Material | AllplanAttributes (SMT), Ortscode_Geschoßbezeichnung | Text1 | ash T_Zarge_Typ | AllplanAttributes (SMT), OKFF | ash T_Tür-Nr. | ash T_Feuchtebeständigkeit | ash T_Sturz | ash T_Zarge_Material | P_ID | AllplanAttributes (SMT), Allright_Bauteil_ID | Gesamtlänge | AllplanAttributes (TGR 1.6), OKFF | ash T_Türprofilnummer | AllplanAttributes (TGR 1.6), Allright_Bauteil_ID | OffsetOpeningBottom | HandicapAccessible | ash T_Strahlenschutz | ash T_Anschlag Gangflügel | AllplanAttributes (SMT), Positionsnummer_Text = AllplanAttributes (TGR 1.6), Positionsnummer_Text
SMT | H2 Ebene +1 | 2.41 | 1.01 | TI-1F-UZ-D-N | E01 | 152 | BZ | 3.75 | E01-096a-001-152 | N | S | - | 1166Rau0000034545 | 1163Mak0812468448 | 8.11 |  | 5 | 1163Mak0814151802 | 150 | no | 0.000000 | - | U100 | AllplanAttributes (SMT) - ash T_Laserschutz: -; ash T_Anschl. an Zuttrittskontrolle: -; Pset_DoorCommon - SecurityRating: SA
SMT | H2 Ebene +1 | 2.41 | 1.01 | TI-1F-UZ-D-N | E01 | 57 | UZ | 3.75 | E01-042a-001-57 | N | - | ST | 1166Rau0000033560 | 1163Mak0812440949 | 8.11 |  | 5 | 1163Mak0814151681 | 150 | no | 0.000000 | - | U100 | AllplanAttributes (SMT) - ash T_Laserschutz: -; ash T_Anschl. an Zuttrittskontrolle: -; Pset_DoorCommon - SecurityRating: SA
SMT | H2 Ebene +1 | 2.41 | 1.01 | TI-1F-UZ-D-N | E01 | 56 | UZ | 3.75 | E01-041a-001-56 | N | - | ST | 1166Rau0000033547 | 1163Mak0812441059 | 8.11 |  | 5 | 1163Mak0814151666 | 150 | no | 0.000000 | - | U100 | AllplanAttributes (SMT) - ash T_Laserschutz: -; ash T_Anschl. an Zuttrittskontrolle: -; Pset_DoorCommon - SecurityRating: SA
SMT | H2 Ebene 0 | 2.46 | 1.135 | TI-1F-UZ-D-N | E00 | 106 | UZ | 0 | E00-068a-001-106 | N | - | ST | 1116Rau0000066838 | 1113Mak0812440141 | 8.335 | 0 | 3 | 1113Mak0813547704 | 200 | no | 0.000000 | - | S68
SMT | H2 Ebene 0 | 2.46 | 1.01 | TI-1F-UZ-D-N | E00 | 141 | UZ | 0 | E00-091a-001-141 | N | - | ST | 1116Rau0000066336 | 1113Mak0812436848 | 8.21 | 0 | 5 | 1113Mak0813548061 | 200 | no | 0.000000 | - | S68
SMT | H2 Ebene 0 | 2.46 | 1.01 | TI-1F-UZ-D-N | E00 | 149 | UZ | 0 | E00-095a-001-149 | N | - | ST | 1116Rau0000066498 | 1113Mak0812436840 | 8.21 | 0 | 5 | 1113Mak0813548070 | 200 | no | 0.000000 | - | S68
SMT | H2 Ebene 0 | 2.46 | 1.01 | TI-1F-UZ-D-N | E00 | 145 | UZ | 0 | E00-093a-001-145 | N | - | ST | 1116Rau0000066330 | 1113Mak0812436856 | 8.21 | 0 | 5 | 1113Mak0813548064 | 200 | no | 0.000000 | - | S68
SMT | H2 Ebene 0 | 2.46 | 1.135 | TI-1F-UZ-D-N | E00 | 144 | UZ | 0 | E00-092a-001-144 | N | - | ST | 1116Rau0000066339 | 1113Mak0812436852 | 8.335 | 0 | 3 | 1113Mak0813547586 | 200 | yes | 0.000000 | - | S68
SMT | H2 Ebene 0 | 2.46 | 1.01 | TI-1F-UZ-D-N | E00 | 148 | UZ | 0 | E00-094a-001-148 | N | - | ST | 1116Rau0000066342 | 1113Mak0812436860 | 8.21 | 0 | 5 | 1113Mak0813548067 | 200 | no | 0.000000 | - | S68
SMT | H2 Ebene 0 | 2.46 | 1.01 | TI-1F-UZ-D-N | E00 | 109 | UZ | 0 | E00-069a-001-109 | N | - | ST | 1116Rau0000065846 | 1113Mak0812436872 | 8.21 | 0 | 5 | 1113Mak0813547966 | 200 | yes | 0.000000 | - | S68
SMT | H2 Ebene 0 | 2.46 | 1.01 | TI-1F-UZ-D-N | E00 | 113 | UZ | 0 | E00-071a-001-113 | N | - | ST | 1116Rau0000065843 | 1113Mak0812436884 | 8.21 | 0 | 5 | 1113Mak0813547972 | 200 | no | 0.000000 | - | S68
SMT | H2 Ebene 0 | 2.46 | 1.135 | TI-1F-UZ-D-N | E00 | 114 | UZ | 0 | E00-072a-001-114 | N | - | ST | 1116Rau0000065840 | 1113Mak0812436880 | 8.335 | 0 | 3 | 1113Mak0813547707 | 200 | yes | 0.000000 | - | S68
SMT | H2 Ebene 0 | 2.46 | 1.01 | TI-1F-UZ-D-N | E00 | 110 | UZ | 0 | E00-070a-001-110 | N | - | ST | 1116Rau0000065886 | 1113Mak0812436876 | 8.21 | 0 | 5 | 1113Mak0813547969 | 200 | no | 0.000000 | - | S68
SMT | H2 Ebene 0 | 2.46 | 1.01 | TI-1F-UZ-D-N | E00 | 64 | UZ | 0 | E00-045a-001-64 | N | - | ST | 1116Rau0000065831 | 1113Mak0812441389 | 8.21 | 0 | 5 | 1113Mak0813547942 | 200 | no | 0.000000 | - | S68 | AllplanAttributes (SMT) - W_Deckenanschluss: Gleitender Deckenanschluss Fall 02; AllplanAttributes (TGR 1.6) - W_Deckenanschluss: Gleitender Deckenanschluss Fall 02
SMT | H2 Ebene 0 | 2.46 | 1.01 | TI-1F-UZ-D-N | E00 | 65 | UZ | 0 | E00-046a-001-65 | N | - | ST | 1116Rau0000065834 | 1113Mak0812441499 | 8.21 | 0 | 5 | 1113Mak0813547945 | 200 | yes | 0.000000 | - | S68 | AllplanAttributes (SMT) - W_Deckenanschluss: Gleitender Deckenanschluss Fall 02; AllplanAttributes (TGR 1.6) - W_Deckenanschluss: Gleitender Deckenanschluss Fall 02
SMT | H2 Ebene 0 | 2.46 | 1.01 | TI-1F-UZ-D-N | E00 | 36 | UZ | 0 | E00-025a-001-36 | N | - | ST | 1116Rau0000066303 | 1113Mak0812445986 | 8.21 | 0 | 5 | 1113Mak0813547885 | 200 | no | 0.000000 | - | S68
SMT | H2 Ebene 0 | 2.46 | 1.01 | TI-1F-UZ-D-N | E00 | 33 | UZ | 0 | E00-024a-001-33 | N | - | ST | 1116Rau0000066300 | 1113Mak0812445990 | 8.21 | 0 | 5 | 1113Mak0813547888 | 200 | no | 0.000000 | - | S68
SMT | H2 Ebene 0 | 2.46 | 1.135 | TI-1F-UZ-D-N | E00 | 32 | UZ | 0 | E00-023a-001-32 | N | - | ST | 1116Rau0000066288 | 1113Mak0812445982 | 8.335 | 0 | 3 | 1113Mak0813547672 | 200 | yes | 0.000000 | - | S68
SMT | H2 Ebene 0 | 2.46 | 1.01 | TI-1F-UZ-D-N | E00 | 29 | UZ | 0 | E00-022a-001-29 | N | - | ST | 1116Rau0000066291 | 1113Mak0812445978 | 8.21 | 0 | 5 | 1113Mak0813547891 | 200 | no | 0.000000 | - | S68
SMT | H2 Ebene 0 | 2.46 | 1.01 | TI-1F-UZ-D-N | E00 | 28 | UZ | 0 | E00-021a-001-28 | N | - | ST | 1116Rau0000066297 | 1113Mak0812445974 | 8.21 | 0 | 5 | 1113Mak0813547906 | 200 | no | 0.000000 | - | S68
SMT | H2 Ebene 0 | 2.46 | 1.01 | TI-1F-UZ-D-N | E00 | 25 | UZ | 0 | E00-020a-001-25 | N | - | ST | 1116Rau0000066294 | 1113Mak0812445970 | 8.21 | 0 | 5 | 1113Mak0813547909 | 200 | no | 0.000000 | - | S68
SMT | H2 Ebene 0 | 2.46 | 1.01 | TI-1F-UZ-D-N | E00 | 24 | UZ | 0 | E00-019a-001-24 | N | - | ST | 1116Rau0000066560 | 1113Mak0812446733 | 8.21 | 0 | 5 | 1113Mak0813547912 | 200 | yes | 0.000000 | - | S68
SMT | H2 Ebene 0 | 2.46 | 1.01 | TI-1F-UZ-D-N | E00 | 117 | UZ | 0 | E00-073a-001-117 | N | - | ST | 1116Rau0000065855 | 1113Mak0812436864 | 8.21 | 0 | 5 | 1113Mak0813547975 | 200 | no | 0.000000 | - | S68
SMT | H2 Ebene 0 | 2.46 | 1.01 | TI-1F-UZ-D-N | E00 | 118 | UZ | 0 | E00-074a-001-118 | - | - | ST | 1116Rau0000065852 | 1113Mak0812436868 | 8.21 | 0 | 5 | 1113Mak0813547978 | 200 | no | 0.000000 | - | S68 | AllplanAttributes (SMT) - ash T_Laserschutz: -; ash T_Anschl. an Zuttrittskontrolle: -; ash T_Material Oberlicht: -; Pset_DoorCommon - SecurityRating: SA
SMT | H2 Ebene 0 | 2.46 | 1.01 | TI-1F-UZ-D-N | E00 | 152 | UZ | 0 | E00-096a-001-152 | N | - | ST | 1116Rau0000066512 | 1113Mak0812468448 | 8.21 | 0 | 5 | 1113Mak0813548085 | 200 | no | 0.000000 | - | S68 | AllplanAttributes (SMT) - ash T_Laserschutz: -; ash T_Anschl. an Zuttrittskontrolle: -
SMT | H2 Ebene 0 | 2.46 | 1.135 | TI-1F-UZ-D-N | E00 | 68 | UZ | 0 | E00-047a-001-68 | N | - | ST | 1116Rau0000066574 | 1113Mak0812441812 | 8.335 | 0 | 3 | 1113Mak0813547695 | 200 | no | 0.000000 | - | S68 | AllplanAttributes (SMT) - W_Deckenanschluss: Gleitender Deckenanschluss Fall 02; AllplanAttributes (TGR 1.6) - W_Deckenanschluss: Gleitender Deckenanschluss Fall 02
SMT | H2 Ebene 0 | 2.46 | 1.01 | TI-1F-UZ-D-N | E00 | 56 | UZ | 0 | E00-041a-001-56 | N | - | ST | 1116Rau0000065759 | 1113Mak0812441059 | 8.21 | 0 | 5 | 1113Mak0813547933 | 200 | no | 0.000000 | - | S68 | AllplanAttributes (SMT) - W_Deckenanschluss: Gleitender Deckenanschluss Fall 02; AllplanAttributes (TGR 1.6) - W_Deckenanschluss: Gleitender Deckenanschluss Fall 02
SMT | H2 Ebene 0 | 2.46 | 1.01 | TI-1F-UZ-D-N | E00 | 57 | UZ | 0 | E00-042a-001-57 | N | - | ST | 1116Rau0000065849 | 1113Mak0812440949 | 8.21 | 0 | 5 | 1113Mak0813547936 | 200 | no | 0.000000 | - | S68 | AllplanAttributes (SMT) - W_Deckenanschluss: Gleitender Deckenanschluss Fall 02; AllplanAttributes (TGR 1.6) - W_Deckenanschluss: Gleitender Deckenanschluss Fall 02
SMT | H2 Ebene 0 | 2.46 | 1.135 | TI-1F-UZ-D-N | E00 | 60 | UZ | 0 | E00-043a-001-60 | N | - | ST | 1116Rau0000065825 | 1113Mak0812441169 | 8.335 | 0 | 3 | 1113Mak0813547692 | 200 | yes | 0.000000 | - | S68 | AllplanAttributes (SMT) - W_Deckenanschluss: Gleitender Deckenanschluss Fall 02; AllplanAttributes (TGR 1.6) - W_Deckenanschluss: Gleitender Deckenanschluss Fall 02
SMT | H2 Ebene 0 | 2.46 | 1.01 | TI-1F-UZ-D-N | E00 | 61 | UZ | 0 | E00-044a-001-61 | N | - | ST | 1116Rau0000065828 | 1113Mak0812441279 | 8.21 | 0 | 5 | 1113Mak0813547939 | 200 | no | 0.000000 | - | S68 | AllplanAttributes (SMT) - W_Deckenanschluss: Gleitender Deckenanschluss Fall 02; AllplanAttributes (TGR 1.6) - W_Deckenanschluss: Gleitender Deckenanschluss Fall 02
SMT | H2 Ebene 0 | 2.46 | 1.01 | TI-1F-UZ-D-N | E00 | 140 | UZ | 0 | E00-090a-001-140 | N | - | ST | 1116Rau0000066333 | 1113Mak0812436844 | 8.21 | 0 | 5 | 1113Mak0813548058 | 200 | no | 0.000000 | - | S68

# IfcDoor: SMT (52)
Type - PredefinedType: DOOR; OperationType: SINGLE_SWING_RIGHT; ParameterTakesPrecedence: no
Type - IfcDoorLiningProperties - LiningDepth: 0.18 m; LiningThickness: 0.04 m
AllplanAttributes (SMT) - Gewerk: Metallbau-, Schlosserarbeiten; V6: 0 m; V7: 0 m; V8: 0 m; V9: 0; Programmversion: 3.1; Objektname: Türmakro; Bezeichnung: SMT; Plugin_Bezeichnung: MainObject; Plugin_Objektname: SmartPartCompressed; Glasanteil_berücksichtigen: 100; Version: 7.21; ash T_Sichtschutz: -; ash R_Verweis Wandansicht: -; ash T_Zulage Schachttür: no; ash T_Panik: -; ash T_Gewerk Los: -; ash T_Erforderl. Durchgangsbreite: 0 m; ash T_Türblatt sichtbar 2D: ja; ash T_Zusatzfunktion Panikschloss: -; ash T_Fluchtwegsicherung: -; ash T_Standflügel-Betätigung: -; ash T_Zusatzfunktion Türschließer: -; ash T_Türschließer-Montage: -; ash T_Feststellanlage (FSA): -; ash T_Zusätzliche Rauchmelder: -; ash T_Zusätzl. Anschluss an BMA: -; ash T_Impulsgeber: -; ash T_Sicherheits-Sensorleisten: -; ash T_Anschl. an Einbruchmeld.anl.: -; ash T_Klemmschutz: -; ash T_LV-Positions-Nr.: -; ash T_Plan-Nr.: -; ash T_Sonstiges, Bemerkungen: -; ash T_nicht abschließbar: no; ash T_Material Seitenteil: -; ash T_Kantengeometrie: 2F; ash T_Kantenmaterial: PU; ash T_Blatt_Oberfläche: HPL; ash T_Erford. Durgangshöhe: 0 m; ash T_Rammschutz: BL; ash T_Fluchtwegrichtung: -; ash T_Lüftungsgitter: 0 m2; ash T_E_Öffner: -; ash T_Automatik_Antrieb: -; ash T_Blatt_Material: HO; ash T_Schlossfunktion: -; ash T_Sonder_Wandmaterial: -; ash T_Anz_Reedkontakte: 0; ash T_Anz_Riegelkontakte: 0; ash T_Bodeneinstand: -; ash T_Blatt_Farbe: -; Attributset-Objekt: Door; Abrechnungsart: St
AllplanQuantities - HeightWindowSillOutside: 0; HeightWindowSillInside: 0; OffsetOpeningTop: 0; OffsetOpeningLeft: 0; OffsetOpeningRight: 0; DeductionOpeningBottom: 100; DeductionOpeningLeft: 40; DeductionOpeningRight: 40; DeductionOpeningTop: 40
Pset_DoorCommon - Status: NEW; IsExternal: no; ThermalTransmittance: 0 W/K/m2; HandicapAccessible: no; FireExit: no
Name | In | OverallHeight (m) | OverallWidth (m) | Material = AllplanAttributes (SMT), Material | AllplanAttributes (SMT), Ortscode_Geschoßbezeichnung | AllplanAttributes (SMT), Text1 | ash T_Dichtschließend | ash T_Zarge_Typ | ash T_Türschließer | AllplanAttributes (SMT), OKFF | ash T_Bodentürstopper | ash T_Tür-Nr. | ash T_Bodendichtung | ash T_Feuchtebeständigkeit | ash T_Sturz | ash T_Schliesszylinder | ash T_Beschlag | ash T_Glasausschnitt | ash T_Schallschutz | ash T_Zarge_Material | ash T_Raum zugehörigkeit | AllplanAttributes (SMT), P_ID | AllplanAttributes (SMT), Allright_Bauteil_ID | AllplanAttributes (TGR 1.6), Codetext | AllplanAttributes (TGR 1.6), V6 (m) = AllplanAttributes (TGR 1.6), V7 (m) = AllplanAttributes (TGR 1.6), V8 (m) = AllplanAttributes (TGR 1.6), V9 | AllplanAttributes (TGR 1.6), Programmversion | AllplanAttributes (TGR 1.6), Objektname | AllplanAttributes (TGR 1.6), Text1 | AllplanAttributes (TGR 1.6), Bezeichnung | AllplanAttributes (TGR 1.6), Plugin_Bezeichnung | AllplanAttributes (TGR 1.6), Plugin_Objektname | AllplanAttributes (TGR 1.6), Gesamtlänge | AllplanAttributes (TGR 1.6), Version | AllplanAttributes (TGR 1.6), OKFF | AllplanAttributes (TGR 1.6), ash T_Türprofilnummer | AllplanAttributes (TGR 1.6), Allright_Bauteil_ID | AllplanAttributes (TGR 1.6), Abrechnungsart | OffsetOpeningBottom | GlassSurface | SmokeStop = SelfClosing | ash T_Anschlag Gangflügel | ash T_Strahlenschutz | AllplanAttributes (SMT), Positionsnummer_Text | AllplanAttributes (TGR 1.6), Positionsnummer_Text
SMT | H2 Ebene +2 | 2.41 | 0.885 | TI-1F-UZ-D | E02 | 49 | no | UZ | OTS | 7.5 | - | E02-032-001-49 | - | F | - | PZ | KD | - | - | ST | BGS | 1215Rau0000006929 | 1213Mak0813004183 | Typ | 0 | 3.1 | TGR-Makro | PlanNo. | TGR 1.6 | MainObject | SmartPartCompressed | 8.035 | 1.6 | 7.5 | 5 | 1213Mak0813223735 | St | 150 | 0 | yes | AllplanAttributes (TGR 1.6) - Ortscode_Geschoßbezeichnung: E02
SMT | H2 Ebene +2 | 2.41 | 0.885 | TI-1F-UZ-D | E02 | 125 | no | UZ | OTS | 7.5 | - | E02-078-001-125 | - | - | - | PZ | KD | - | - | ST | BGS | 1215Rau0000006932 | 1213Mak0813004371 | Typ | 0 | 3.1 | TGR-Makro | PlanNo. | TGR 1.6 | MainObject | SmartPartCompressed | 8.035 | 1.6 | 7.5 | 5 | 1213Mak0813223970 | St | 150 | 0 | yes | AllplanAttributes (TGR 1.6) - Ortscode_Geschoßbezeichnung: E02
SMT | H2 Ebene +2 | 2.41 | 1.01 | TI-1F-UZ-D | E02 | 135 | no | UZ | OTS | 7.5 | - | E02-087-001-135 | - | - | - | PZ | KD | - | - | ST | BGS | 1215Rau0000006893 | 1213Mak0813004784 | Typ | 0 | 3.1 | TGR-Makro | PlanNo. | TGR 1.6 | MainObject | SmartPartCompressed | 8.16 | 1.6 | 7.5 | 5 | 1213Mak0813223955 | St | 150 | 0 | yes | AllplanAttributes (TGR 1.6) - Ortscode_Geschoßbezeichnung: E02; Pset_DoorCommon - FireRating: EI2 30
SMT | H2 Ebene +2 | 2.41 | 1.01 | TI-1F-UZ-D | E02 | 136 | no | UZ | OTS | 7.5 | - | E02-088-001-136 | - | - | - | PZ | KD | - | - | ST | BGS | 1215Rau0000006893 | 1213Mak0813004790 | Typ | 0 | 3.1 | TGR-Makro | PlanNo. | TGR 1.6 | MainObject | SmartPartCompressed | 8.16 | 1.6 | 7.5 | 5 | 1213Mak0813223952 | St | 150 | 0 | yes | AllplanAttributes (TGR 1.6) - Ortscode_Geschoßbezeichnung: E02; Pset_DoorCommon - FireRating: EI2 30
SMT | H2 Ebene +2 | 2.41 | 0.885 | TI-1F-UZ-D | E02 | 83 | yes | UZ | - | 7.5 | W | E02-052b-001-83 | - | F | - | WC | DD | - | - | ST | BGS | 1216Rau0000046537 | 1213Mak0813004194 | Typ | 0 | 3.1 | TGR-Makro | PlanNo. | TGR 1.6 | MainObject | SmartPartCompressed | 7.985 | 1.6 | 7.5 | 5 | 1213Mak0813224164 | St | 150 | 0 | no | - | AllplanAttributes (TGR 1.6) - Ortscode_Geschoßbezeichnung: E02; Pset_DoorCommon - FireRating: -; AllplanAttributes (SMT) - ash T_Unterschnitt: 1
SMT | H2 Ebene +2 | 2.41 | 0.885 | TI-1F-UZ-D | E02 | 84 | no | UZ | - | 7.5 | W | E02-052a-001-84 | - | F | - | WC | DD | - | - | ST | BGS | 1216Rau0000046537 | 1213Mak0813004189 | Typ | 0 | 3.1 | TGR-Makro | PlanNo. | TGR 1.6 | MainObject | SmartPartCompressed | 7.985 | 1.6 | 7.5 | 5 | 1213Mak0813224161 | St | 150 | 0 | no | - | AllplanAttributes (TGR 1.6) - Ortscode_Geschoßbezeichnung: E02; Pset_DoorCommon - FireRating: -; AllplanAttributes (SMT) - ash T_Unterschnitt: 1
SMT | H2 Ebene +2 | 2.41 | 1.01 | TI-1F-UZ-D | E02 | 38 | no | UZ | OTS | 7.5 | - | E02-027-001-38 | - | - | - | PZ | KD | - | - | ST | BGS | 1215Rau0000006926 | 1213Mak0813004679 | Typ | 0 | 3.1 | TGR-Makro | PlanNo. | TGR 1.6 | MainObject | SmartPartCompressed | 8.16 | 1.6 | 7.5 | 5 | 1213Mak0813223767 | St | 150 | 0 | yes | AllplanAttributes (TGR 1.6) - Ortscode_Geschoßbezeichnung: E02; Pset_DoorCommon - FireRating: EI2 30
SMT | H2 Ebene +2 | 2.41 | 1.01 | TI-1F-UZ-D | E02 | 39 | no | UZ | OTS | 7.5 | - | E02-028-001-39 | - | - | - | PZ | KD | - | - | ST | BGS | 1215Rau0000006926 | 1213Mak0813004685 | Typ | 0 | 3.1 | TGR-Makro | PlanNo. | TGR 1.6 | MainObject | SmartPartCompressed | 8.16 | 1.6 | 7.5 | 5 | 1213Mak0813223770 | St | 150 | 0 | yes | AllplanAttributes (TGR 1.6) - Ortscode_Geschoßbezeichnung: E02; Pset_DoorCommon - FireRating: EI2 30
SMT | H2 Ebene +2 | 2.41 | 1.26 | TI-1F-UZ-D | E02 | 167 | no | UZ | OTS | 7.5 | - | E02-012a-001-167 | - | - | - | PZ | DK | 35x100 | 37 dB | ST | BGS | 1216Rau0000046616 | 1213Mak0813004171 | Typ | 0 | 3.1 | TGR-Makro | PlanNo. | TGR 1.6 | MainObject | SmartPartCompressed | 8.41 | 1.6 | 7.5 | 2 | 1213Mak0813225756 | St | 150 | 0 | yes | AllplanAttributes (TGR 1.6) - Ortscode_Geschoßbezeichnung: E02; Pset_DoorCommon - FireRating: EI2 30; AllplanAttributes (SMT) - ash T_Anschl. an Zuttrittskontrolle: -
SMT | H2 Ebene +2 | 2.41 | 1.26 | TI-1F-UZ-D | E02 | 156 | no | UZ | OTS | 7.5 | - | E02-064a-001-156 | - | - | - | PZ | DK | 35x100 | 37 dB | ST | BGS | 1216Rau0000046836 | 1213Mak0813004177 | Typ | 0 | 3.1 | TGR-Makro | PlanNo. | TGR 1.6 | MainObject | SmartPartCompressed | 8.41 | 1.6 | 7.5 | 2 | 1213Mak0813223896 | St | 150 | 0 | yes | AllplanAttributes (TGR 1.6) - Ortscode_Geschoßbezeichnung: E02; Pset_DoorCommon - FireRating: EI2 30; AllplanAttributes (SMT) - ash T_Anschl. an Zuttrittskontrolle: -
SMT | H2 Ebene +2 | 2.41 | 1.01 | TI-1F-UZ-D | E02 | 103 | no | UZ | - | 7.5 | W | E02-057-001-103 | Ja | - | - | PZ | KD | - | 37 dB | ST | BGS | 1216Rau0000047119 | 1213Mak0813004229 | Typ | 0 | 3.1 | TGR-Makro | PlanNo. | TGR 1.6 | MainObject | SmartPartCompressed | 8.11 | 1.6 | 7.5 | 5 | 1213Mak0813223994 | St | 150 | 0 | no | AllplanAttributes (TGR 1.6) - Ortscode_Geschoßbezeichnung: E02
SMT | H2 Ebene +2 | 2.41 | 1.01 | TI-1F-UZ-D | E02 | 72 | no | UZ | - | 7.5 | W | E02-006-001-72 | Ja | - | - | PZ | KD | - | - | ST | BGS | 1216Rau0000046473 | 1213Mak0813004214 | Typ | 0 | 3.1 | TGR-Makro | PlanNo. | TGR 1.6 | MainObject | SmartPartCompressed | 8.11 | 1.6 | 7.5 | 5 | 1213Mak0813223824 | St | 150 | 0 | no | AllplanAttributes (TGR 1.6) - Ortscode_Geschoßbezeichnung: E02
SMT | H2 Ebene +2 | 2.41 | 0.885 | TI-1F-UZ-D | E02 | 166 | yes | UZ | - | 7.5 | - | E02-012b-001-166 | - | F | - | WC | DD | - | 37 dB | ST | BGS | 1216Rau0000046651 | 1213Mak0813004499 | Typ | 0 | 3.1 | TGR-Makro | PlanNo. | TGR 1.6 | MainObject | SmartPartCompressed | 7.985 | 1.6 | 7.5 | 5 | 1213Mak0813223876 | St | 150 | 0 | no | AllplanAttributes (TGR 1.6) - Ortscode_Geschoßbezeichnung: E02; AllplanAttributes (SMT) - ash T_Unterschnitt: 1; ash T_Anschl. an Zuttrittskontrolle: -
SMT | H2 Ebene +2 | 2.41 | 1.01 | TI-1F-UZ-D | E02 | 41 | yes | UZ | - | 7.5 | - | E02-037-001-41 | Ja | - | - | PZ | DK | - | 27 dB | ST | BS | 1216Rau0000046125 | 1213Mak0813563071 | Typ | 0 | 3.1 | TGR-Makro | PlanNo. | TGR 1.6 | MainObject | SmartPartCompressed | 8.16 | 1.6 | 7.5 | 5 | 1213Mak0813563067 | St | 150 | 0 | no | - | 0.000000 | AllplanAttributes (TGR 1.6) - Ortscode_Geschoßbezeichnung: E02; AllplanAttributes (SMT) - ash T_Anschl. an Zuttrittskontrolle: -
SMT | H2 Ebene +2 | 2.41 | 1.01 | TI-1F-UZ-D | E02 | 133 | yes | UZ | - | 7.5 | - | E02-082-001-133 | Ja | - | - | PZ | DK | - | 27 dB | ST | BS | 1216Rau0000047485 | 1213Mak0813004329 | Typ | 0 | 3.1 | TGR-Makro | PlanNo. | TGR 1.6 | MainObject | SmartPartCompressed | 8.16 | 1.6 | 7.5 | 5 | 1213Mak0813226668 | St | 150 | 0 | no | AllplanAttributes (TGR 1.6) - Ortscode_Geschoßbezeichnung: E02; AllplanAttributes (SMT) - ash T_Anschl. an Zuttrittskontrolle: -
SMT | H2 Ebene +2 | 2.41 | 0.885 | TI-1F-UZ-D | E02 | 157 | yes | UZ | - | 7.5 | - | E02-064b-001-157 | - | F | - | WC | DD | - | 37 dB | ST | BGS | 1216Rau0812652342 | 1213Mak0813004494 | Typ | 0 | 3.1 | TGR-Makro | PlanNo. | TGR 1.6 | MainObject | SmartPartCompressed | 7.985 | 1.6 | 7.5 | 5 | 1213Mak0813223879 | St | 150 | 0 | no | AllplanAttributes (TGR 1.6) - Ortscode_Geschoßbezeichnung: E02; AllplanAttributes (SMT) - ash T_Unterschnitt: 1
SMT | H2 Ebene +2 | 2.41 | 1.26 | TI-1F-UZ-D | E02 | 169 | no | UZ | - | 7.5 | - | E02-012-002-169 | - | - | - | PZ | KD | - | 37 dB | ST | BGS | 1216Rau0000046637 | 1213Mak0813004224 | Typ | 0 | 3.1 | TGR-Makro | PlanNo. | TGR 1.6 | MainObject | SmartPartCompressed | 8.36 | 1.6 | 7.5 | 3 | 1213Mak0813223861 | St | 150 | 0 | no | AllplanAttributes (TGR 1.6) - Ortscode_Geschoßbezeichnung: E02
SMT | H2 Ebene +1 | 2.41 | 0.885 | TI-1F-UZ-ZK | E01 | 49 | no | UZ | OTS | 3.75 | - | E01-032-001-49 | - | F | - | PZ | KD | - | - | ST | BGS | 1165Rau0000004677 | 1163Mak0812440434 | Typ | 0 | 3.1 | TGR-Makro | PlanNo. | TGR 1.6 | MainObject | SmartPartCompressed | 8.035 | 1.6 |  |  | 1163Mak0814152548 | St | 150 | 0 | yes | - | 0.000000 | U100 | U100
SMT | H2 Ebene +1 | 2.41 | 0.885 | TI-1F-UZ-ZK | E01 | 125 | no | UZ | OTS | 3.75 | - | E01-078-001-125 | - | - | - | PZ | KD | - | - | ST | BGS | 1165Rau0000004725 | 1163Mak0812436415 | Typ | 0 | 3.1 | TGR-Makro | PlanNo. | TGR 1.6 | MainObject | SmartPartCompressed | 8.035 | 1.6 |  | 5 | 1163Mak0814151895 | St | 150 | 0 | yes | - | 0.000000 | U100 | U100
SMT | H2 Ebene +1 | 2.41 | 1.01 | TI-1F-UZ-ZK | E01 | 135 | no | UZ | OTS | 3.75 | - | E01-087-001-135 | - | - | - | PZ | KD | - | - | ST | BGS | 1165Rau0000004736 | 1163Mak0812549653 | Typ | 0 | 3.1 | TGR-Makro | PlanNo. | TGR 1.6 | MainObject | SmartPartCompressed | 8.16 | 1.6 |  | 5 | 1163Mak0814151832 | St | 150 | 0 | yes | - | 0.000000 | U100 | U100 | Pset_DoorCommon - FireRating: EI2 30
SMT | H2 Ebene +1 | 2.41 | 1.01 | TI-1F-UZ-ZK | E01 | 136 | no | UZ | OTS | 3.75 | - | E01-088-001-136 | - | - | - | PZ | KD | - | - | ST | BGS | 1165Rau0000004736 | 1163Mak0812549650 | Typ | 0 | 3.1 | TGR-Makro | PlanNo. | TGR 1.6 | MainObject | SmartPartCompressed | 8.16 | 1.6 |  | 5 | 1163Mak0814151847 | St | 150 | 0 | yes | - | 0.000000 | U100 | U100 | Pset_DoorCommon - FireRating: EI2 30
SMT | H2 Ebene +1 | 2.41 | 1.01 | TI-1F-UZ-ZK | E01 | 39 | no | UZ | OTS | 3.75 | - | E01-028-001-39 | - | - | - | PZ | KD | - | - | ST | BGS | 1165Rau0000004651 | 1163Mak0812742641 | Typ | 0 | 3.1 | TGR-Makro | PlanNo. | TGR 1.6 | MainObject | SmartPartCompressed | 8.16 | 1.6 |  | 5 | 1163Mak0814151723 | St | 150 | 0 | yes | - | 0.000000 | U100 | U100 | Pset_DoorCommon - FireRating: EI2 30
SMT | H2 Ebene +1 | 2.41 | 1.01 | TI-1F-UZ-ZK | E01 | 38 | no | UZ | OTS | 3.75 | - | E01-027-001-38 | - | - | - | PZ | KD | - | - | ST | BGS | 1165Rau0000004651 | 1163Mak0812742620 | Typ | 0 | 3.1 | TGR-Makro | PlanNo. | TGR 1.6 | MainObject | SmartPartCompressed | 8.16 | 1.6 |  | 5 | 1163Mak0814151720 | St | 150 | 0 | yes | - | 0.000000 | U100 | U100 | Pset_DoorCommon - FireRating: EI2 30
SMT | H2 Ebene +1 | 2.41 | 1.26 | TI-1F-UZ-D | E01 | 156 | no | UZ | OTS | 3.75 | - | E01-064a-001-156 | - | - | - | PZ | DK | 35x100 | 37 dB | ST | BGS | 1166Rau0000034701 | 1163Mak0812535689 | Typ | 0 | 3.1 | TGR-Makro | PlanNo. | TGR 1.6 | MainObject | SmartPartCompressed | 8.41 | 1.6 |  | 2 | 1163Mak0814295399 | St | 150 | 0 | yes | - | 0.000000 | U100 | U100 | Pset_DoorCommon - FireRating: EI2 30; SecurityRating: 1; AllplanAttributes (SMT) - ash T_Anschl. an Zuttrittskontrolle: -
SMT | H2 Ebene +1 | 2.41 | 0.885 | TI-1F-UZ-D-N | E01 | 157 | yes | BZ | - | 3.75 | - | E01-064b-001-157 | - | F | S | WC | DD | - | 37 dB | - | BGS | 1166Rau0000042128 | 1163Mak0812435746 | Typ | 0 | 3.1 | TGR-Makro | PlanNo. | TGR 1.6 | MainObject | SmartPartCompressed | 7.985 | 1.6 |  | 5 | 1163Mak0814151799 | St | 150 | 0 | no | - | 0.000000 | U100 | U100 | AllplanAttributes (SMT) - ash T_Unterschnitt: 1
SMT | H2 Ebene +1 | 2.41 | 0.885 | TI-1F-UZ-D-N | E01 | 166 | yes | UZ | - | 3.75 | - | E01-012b-001-166 | - | F | - | WC | DD | - | 37 dB | ST | BGS | 1166Rau0000033238 | 1163Mak0812435799 | Typ | 0 | 3.1 | TGR-Makro | PlanNo. | TGR 1.6 | MainObject | SmartPartCompressed | 7.985 | 1.6 |  | 5 | 1163Mak0814151784 | St | 150 | 0 | no | - | 0.000000 | U100 | U100 | AllplanAttributes (SMT) - ash T_Unterschnitt: 1; ash T_Anschl. an Zuttrittskontrolle: -
SMT | H2 Ebene +1 | 2.41 | 1.01 | TI-1F-UZ-ZK | E01 | 41 | yes | UZ | - | 3.75 | - | E01-037-001-41 | Ja | - | - | PZ | DK | - | 27 dB | ST | BS | 1166Rau0000033512 | 1163Mak0814484062 | Typ | 0 | 3.1 | TGR-Makro | PlanNo. | TGR 1.6 | MainObject | SmartPartCompressed | 8.16 | 1.6 |  | 5 | 1163Mak0814484049 | St | 150 | 0 | no | - | 0.000000 | U100 | U100 | AllplanAttributes (SMT) - ash T_Anschl. an Zuttrittskontrolle: -
SMT | H2 Ebene +1 | 2.41 | 1.01 | TI-1F-UZ-ZK | E01 | 133 | yes | BZ | - | 3.75 | - | E01-082-001-133 | Ja | - | S | PZ | DK | - | 27 dB | - | BS | 1166Rau0000034316 | 1163Mak0812496644 | Typ | 0 | 3.1 | TGR-Makro | PlanNo. | TGR 1.6 | MainObject | SmartPartCompressed | 8.16 | 1.6 |  | 5 | 1163Mak0814151850 | St | 150 | 0 | no | - | 0.000000 | U100 | U100 | AllplanAttributes (SMT) - ash T_Anschl. an Zuttrittskontrolle: -
SMT | H2 Ebene +1 | 2.41 | 1.26 | TI-1F-UZ-D | E01 | 167 | no | UZ | OTS | 3.75 | - | E01-012a-001-167 | - | - | - | PZ | DK | 35x100 | 37 dB | ST | BGS | 1166Rau0000034690 | 1163Mak0812446960 | Typ | 0 | 3.1 | TGR-Makro | PlanNo. | TGR 1.6 | MainObject | SmartPartCompressed | 8.41 | 1.6 |  | 2 | 1163Mak0814151159 | St | 150 | 0 | yes | - | 0.000000 | U100 | U100 | Pset_DoorCommon - FireRating: EI2 30; SecurityRating: 1; AllplanAttributes (SMT) - ash T_Anschl. an Zuttrittskontrolle: -
SMT | H2 Ebene +1 | 2.41 | 1.01 | TI-1F-UZ-ZK | E01 | 72 | no | UZ | - | 3.75 | W | E01-006-001-72 | Ja | - | - | PZ | KD | - | - | ST | BGS | 1166Rau0000034580 | 1163Mak0812435694 | Typ | 0 | 3.1 | TGR-Makro | PlanNo. | TGR 1.6 | MainObject | SmartPartCompressed | 8.11 | 1.6 |  | 5 | 1163Mak0814151901 | St | 150 | 0 | no | - | 0.000000 | U100 | U100
SMT | H2 Ebene +1 | 2.41 | 0.885 | TI-1F-UZ-D-N | E01 | 84 | no | UZ | - | 3.75 | W | E01-052a-001-84 | - | F | - | WC | DD | - | - | ST | BS | 1166Rau0000034712 | 1163Mak0812435687 | Typ | 0 | 3.1 | TGR-Makro | PlanNo. | TGR 1.6 | MainObject | SmartPartCompressed | 7.985 | 1.6 |  | 5 | 1163Mak0814180024 | St | 150 | 0 | no | - | 0.000000 | U100 | U100 | Pset_DoorCommon - FireRating: -; AllplanAttributes (SMT) - ash T_Unterschnitt: 1
SMT | H2 Ebene +1 | 2.41 | 0.885 | TI-1F-UZ-D-N | E01 | 83 | yes | UZ | - | 3.75 | W | E01-052b-001-83 | - | F | - | WC | DD | - | - | ST | BS | 1166Rau0000034712 | 1163Mak0812435683 | Typ | 0 | 3.1 | TGR-Makro | PlanNo. | TGR 1.6 | MainObject | SmartPartCompressed | 7.985 | 1.6 |  | 5 | 1163Mak0814180021 | St | 150 | 0 | no | - | 0.000000 | U100 | U100 | Pset_DoorCommon - FireRating: -; AllplanAttributes (SMT) - ash T_Unterschnitt: 1
SMT | H2 Ebene +1 | 2.41 | 1.01 | TI-1F-UZ-ZK | E01 | 103 | no | - | - | 3.75 | W | E01-057-001-103 | Ja | - | - | PZ | KD | - | 37 dB | - | BGS | 1166Rau0000034564 | 1163Mak0812833391 | Typ | 0 | 3.1 | TGR-Makro | PlanNo. | TGR 1.6 | MainObject | SmartPartCompressed | 8.11 | 1.6 |  | 5 | 1163Mak0814151865 | St | 150 | 0 | no | - | 0.000000 | U100 | U100
SMT | H2 Ebene +1 | 2.41 | 1.26 | TI-1F-UZ-ZK | E01 | 169 | no | UZ | - | 3.75 | - | E01-012-002-169 | - | - | - | PZ | KD | - | 37 dB | ST | BGS | 1166Rau0000033275 | 1163Mak0812447070 | Typ | 0 | 3.1 | TGR-Makro | PlanNo. | TGR 1.6 | MainObject | SmartPartCompressed | 8.36 | 1.6 |  | 3 | 1163Mak0814151191 | St | 150 | 0 | no | - | 0.000000 | U100 | U100
SMT | H2 Ebene +1 | 2.41 | 1.26 | TI-1F-UZ-ZK | E01 | 154 | no | UZ | - | 3.75 | - | E01-064-001-154 | - | - | - | PZ | KD | - | 37 dB | ST | BGS | 1166Rau0000034214 | 1163Mak0812447093 | Typ | 0 | 3.1 | TGR-Makro | PlanNo. | TGR 1.6 | MainObject | SmartPartCompressed | 8.36 | 1.6 |  | 3 | 1163Mak0814151194 | St | 150 | 0 | no | - | 0.000000 | U100 | U100
SMT | H2 Ebene 0 | 2.46 | 0.885 | TI-1F-UZ-ZK | E00 | 49 | no | UZ | OTS | 0 | - | E00-032-001-49 | - | F | - | PZ | KD | - | - | ST | BGS | 1115Rau0000005065 | 1113Mak0812440434 | Typ | 0 | 3.1 | TGR-Makro | PlanNo. | TGR 1.6 | MainObject | SmartPartCompressed | 8.135 | 1.6 | 0 | 5 | 1113Mak0813548124 | St | 200 | 0 | yes | - | 0.000000 | S68 | S68
SMT | H2 Ebene 0 | 2.46 | 0.885 | TI-1F-UZ-ZK | E00 | 125 | no | UZ | OTS | 0 | - | E00-078-001-125 | - | - | - | PZ | KD | - | - | ST | BGS | 1115Rau0000005072 | 1113Mak0812436415 | Typ | 0 | 3.1 | TGR-Makro | PlanNo. | TGR 1.6 | MainObject | SmartPartCompressed | 8.135 | 1.6 | 0 | 5 | 1113Mak0813547993 | St | 200 | 0 | yes | - | 0.000000 | S68 | S68
SMT | H2 Ebene 0 | 2.46 | 1.01 | TI-1F-UZ-ZK | E00 | 136 | no | UZ | OTS | 0 | - | E00-088-001-136 | - | - | - | PZ | KD | - | - | ST | BGS | 1115Rau0000005201 | 1113Mak0812549650 | Typ | 0 | 3.1 | TGR-Makro | PlanNo. | TGR 1.6 | MainObject | SmartPartCompressed | 8.26 | 1.6 | 0 | 5 | 1113Mak0813548011 | St | 200 | 0 | yes | - | 0.000000 | S68 | S68 | Pset_DoorCommon - FireRating: EI2 30
SMT | H2 Ebene 0 | 2.46 | 1.01 | TI-1F-UZ-ZK | E00 | 135 | no | UZ | OTS | 0 | - | E00-087-001-135 | - | - | - | PZ | KD | - | - | ST | BGS | 1115Rau0000005201 | 1113Mak0812549653 | Typ | 0 | 3.1 | TGR-Makro | PlanNo. | TGR 1.6 | MainObject | SmartPartCompressed | 8.26 | 1.6 | 0 | 5 | 1113Mak0813548008 | St | 200 | 0 | yes | - | 0.000000 | S68 | S68 | Pset_DoorCommon - FireRating: EI2 30
SMT | H2 Ebene 0 | 2.46 | 0.885 | TI-1F-UZ-D-N | E00 | 83 | yes | UZ | - | 0 | W | E00-052b-001-83 | - | F | - | WC | DD | - | - | ST | BGS | 1116Rau0000069152 | 1113Mak0812435683 | Typ | 0 | 3.1 | TGR-Makro | PlanNo. | TGR 1.6 | MainObject | SmartPartCompressed | 8.085 | 1.6 | 0 | 5 | 1113Mak0813547960 | St | 200 | 0 | no | - | 0.000000 | S68 | S68 | Pset_DoorCommon - FireRating: -; AllplanAttributes (SMT) - ash T_Unterschnitt: 1
SMT | H2 Ebene 0 | 2.46 | 0.885 | TI-1F-UZ-D-N | E00 | 84 | no | UZ | - | 0 | W | E00-052a-001-84 | - | F | - | WC | DD | - | - | ST | BGS | 1116Rau0000069152 | 1113Mak0812435687 | Typ | 0 | 3.1 | TGR-Makro | PlanNo. | TGR 1.6 | MainObject | SmartPartCompressed | 8.085 | 1.6 | 0 | 5 | 1113Mak0813547963 | St | 200 | 0 | no | - | 0.000000 | S68 | S68 | Pset_DoorCommon - FireRating: -; AllplanAttributes (SMT) - ash T_Unterschnitt: 1
SMT | H2 Ebene 0 | 2.46 | 1.01 | TI-1F-UZ-ZK | E00 | 39 | no | UZ | OTS | 0 | - | E00-028-001-39 | - | - | - | PZ | KD | - | - | ST | BGS | 1115Rau0000005119 | 1113Mak0812742641 | Typ | 0 | 3.1 | TGR-Makro | PlanNo. | TGR 1.6 | MainObject | SmartPartCompressed | 8.26 | 1.6 | 0 | 5 | 1113Mak0813547930 | St | 200 | 0 | yes | - | 0.000000 | S68 | S68 | Pset_DoorCommon - FireRating: EI2 30
SMT | H2 Ebene 0 | 2.46 | 1.01 | TI-1F-UZ-ZK | E00 | 38 | no | UZ | OTS | 0 | - | E00-027-001-38 | - | - | - | PZ | KD | - | - | ST | BGS | 1115Rau0000005119 | 1113Mak0812742620 | Typ | 0 | 3.1 | TGR-Makro | PlanNo. | TGR 1.6 | MainObject | SmartPartCompressed | 8.26 | 1.6 | 0 | 5 | 1113Mak0813547927 | St | 200 | 0 | yes | - | 0.000000 | S68 | S68 | Pset_DoorCommon - FireRating: EI2 30
SMT | H2 Ebene 0 | 2.46 | 1.01 | TI-1F-UZ-ZK | E00 | 72 | no | UZ | - | 0 | W | E00-006-001-72 | Ja | - | - | PZ | KD | - | - | ST | BGS | 1116Rau0000227279 | 1113Mak0812435694 | Typ | 0 | 3.1 | TGR-Makro | PlanNo. | TGR 1.6 | MainObject | SmartPartCompressed | 8.21 | 1.6 | 0 | 5 | 1113Mak0813548118 | St | 200 | 0 | no | - | 0.000000 | S68 | S68
SMT | H2 Ebene 0 | 2.46 | 1.01 | TI-1F-UZ-ZK | E00 | 103 | no | UZ | - | 0 | W | E00-057-001-103 | Ja | - | - | PZ | KD | - | 37 dB | ST | BGS | 1116Rau0000227242 | 1113Mak0812833391 | Typ | 0 | 3.1 | TGR-Makro | PlanNo. | TGR 1.6 | MainObject | SmartPartCompressed | 8.21 | 1.6 | 0 | 5 | 1113Mak0813548142 | St | 200 | 0 | no | - | 0.000000 | S68 | S68
SMT | H2 Ebene 0 | 2.46 | 1.26 | TI-1F-UZ-D | E00 | 156 | no | UZ | OTS | 0 | - | E00-064a-001-156 | - | - | - | PZ | DK | 35x100 | 37 dB | ST | BGS | 1116Rau0000066768 | 1113Mak0812535689 | Typ | 0 | 3.1 | TGR-Makro | PlanNo. | TGR 1.6 | MainObject | SmartPartCompressed | 8.51 | 1.6 | 0 | 2 | 1113Mak0813547620 | St | 200 | 0.35875 | yes | - | 0.000000 | S68 | S68 | Pset_DoorCommon - FireRating: EI2 30; SecurityRating: 1; AllplanAttributes (SMT) - ash T_Anschl. an Zuttrittskontrolle: -; ash T_Laserschutz: -
SMT | H2 Ebene 0 | 2.46 | 0.885 | TI-1F-UZ-D-N | E00 | 157 | yes | UZ | - | 0 | - | E00-064b-001-157 | - | F | - | WC | DD | - | 37 dB | ST | BGS | 1116Rau0000066771 | 1113Mak0812435746 | Typ | 0 | 3.1 | TGR-Makro | PlanNo. | TGR 1.6 | MainObject | SmartPartCompressed | 8.085 | 1.6 | 0 | 5 | 1113Mak0813548100 | St | 200 | 0 | no | - | 0.000000 | S68 | S68 | AllplanAttributes (SMT) - ash T_Unterschnitt: 1
SMT | H2 Ebene 0 | 2.46 | 1.01 | TI-1F-UZ-ZK | E00 | 41 | yes | UZ | - | 0 | - | E00-037-001-41 | Ja | - | - | PZ | DK | - | 27 dB | ST | BS | 1116Rau0000066366 | 1113Mak0814045829 | Typ | 0 | 3.1 | TGR-Makro | PlanNo. | TGR 1.6 | MainObject | SmartPartCompressed | 8.26 | 1.6 | 0 | 5 | 1113Mak0814045827 | St | 200 | 0 | no | - | 0.000000 | S68 | S68 | AllplanAttributes (SMT) - ash T_Anschl. an Zuttrittskontrolle: -; ash T_Laserschutz: -
SMT | H2 Ebene 0 | 2.46 | 0.885 | TI-1F-UZ-D-N | E00 | 166 | yes | UZ | - | 0 | - | E00-012b-001-166 | - | F | - | WC | DD | - | 37 dB | ST | BGS | 1116Rau0000066462 | 1113Mak0812435799 | Typ | 0 | 3.1 | TGR-Makro | PlanNo. | TGR 1.6 | MainObject | SmartPartCompressed | 8.085 | 1.6 | 0 | 5 | 1113Mak0813548103 | St | 200 | 0 | no | - | 0.000000 | S68 | S68 | AllplanAttributes (SMT) - ash T_Unterschnitt: 1; ash T_Anschl. an Zuttrittskontrolle: -; ash T_Laserschutz: -
SMT | H2 Ebene 0 | 2.46 | 1.26 | TI-1F-UZ-D | E00 | 167 | no | UZ | OTS | 0 | - | E00-012a-001-167 | - | - | - | PZ | DK | 35x100 | 37 dB | ST | BGS | 1116Rau0000066636 | 1113Mak0812446960 | Typ | 0 | 3.1 | TGR-Makro | PlanNo. | TGR 1.6 | MainObject | SmartPartCompressed | 8.51 | 1.6 | 0 | 2 | 1113Mak0813547637 | St | 200 | 0.35875 | yes | - | 0.000000 | S68 | S68 | Pset_DoorCommon - FireRating: EI2 30; SecurityRating: 1; AllplanAttributes (SMT) - ash T_Anschl. an Zuttrittskontrolle: -; ash T_Laserschutz: -
SMT | H2 Ebene 0 | 2.46 | 1.26 | TI-1F-UZ-ZK | E00 | 154 | no | UZ | - | 0 | - | E00-064-001-154 | - | - | - | PZ | KD | - | 37 dB | ST | BGS | 1116Rau0000066588 | 1113Mak0812447093 | Typ | 0 | 3.1 | TGR-Makro | PlanNo. | TGR 1.6 | MainObject | SmartPartCompressed | 8.46 | 1.6 | 0 | 3 | 1113Mak0813547603 | St | 200 | 0 | no | - | 0.000000 | S68 | S68
SMT | H2 Ebene 0 | 2.46 | 1.26 | TI-1F-UZ-ZK | E00 | 169 | no | UZ | - | 0 | - | E00-012-002-169 | - | - | - | PZ | KD | - | 37 dB | ST | BGS | 1116Rau0000066624 | 1113Mak0812447070 |  |  |  |  |  |  |  |  |  |  |  |  |  |  | 200 | 0 | no | - | 0.000000 | S68 | AllplanAttributes (SMT) - ash T_Laserschutz: -; AllplanAttributes (TGR 1.5) - Codetext: Typ; V6: 0 m; V7: 0 m; V8: 0 m; V9: 0; Programmversion: 3.1; Objektname: TGR-Makro; Text1: PlanNo.; Bezeichnung: TGR 1.5; Plugin_Bezeichnung: MainObject; Plugin_Objektname: SmartPartCompressed; Gesamtlänge: 12.3825; Version: 1.5; ash T_Türprofilnummer: 3; Positionsnummer_Text: U100; P_ID: 1166Rau0000034222; Allright_Bauteil_ID: 1113Mak0814244112; Abrechnungsart: St

# IfcDoor: SMT (2)
In: H2 Ebene 0
Type - PredefinedType: DOOR; OperationType: SINGLE_SWING_RIGHT; ParameterTakesPrecedence: no
Type - IfcDoorLiningProperties - LiningDepth: 0.2 m; LiningThickness: 0.05 m
OverallHeight: 2.72 m; OverallWidth: 1.35 m; Material: TA-1F-AG-D-O
AllplanAttributes (SMT) - Gewerk: Metallbau-, Schlosserarbeiten; V6: 0 m; V7: 0 m; V8: 0 m; V9: 0; Ortscode_Geschoßbezeichnung: E00; Programmversion: 3.0; Objektname: Türmakro; Bezeichnung: SMT; Material: TA-1F-AG-D-O; Plugin_Bezeichnung: MainObject; Plugin_Objektname: SmartPartCompressed; Glasanteil_berücksichtigen: 100; Version: 8.11; ash T_Unterschnitt: -; ash T_Sichtschutz: -; ash R_Verweis Wandansicht: -; ash T_Panik: -; ash T_Zarge_Typ: -; ash T_Türschließer: -; ash T_Gewerk Los: -; ash T_Erforderl. Durchgangsbreite: 0 m; ash T_Türblatt sichtbar 2D: ja; ash T_Zusatzfunktion Panikschloss: -; ash T_Fluchtwegsicherung: -; ash T_Standflügel-Betätigung: -; ash T_Zusatzfunktion Türschließer: -; ash T_Türschließer-Montage: -; ash T_Feststellanlage (FSA): -; ash T_Zusätzliche Rauchmelder: -; ash T_Zusätzl. Anschluss an BMA: -; ash T_Impulsgeber: -; ash T_Sicherheits-Sensorleisten: -; ash T_Anschl. an Zuttrittskontrolle: -; ash T_Anschl. an Einbruchmeld.anl.: -; ash T_Klemmschutz: -; ash T_LV-Positions-Nr.: -; ash T_Plan-Nr.: -; ash T_Sonstiges, Bemerkungen: -; OKFF: 0; ash T_Bodentürstopper: -; ash T_Material Seitenteil: -; ash T_Strahlenschutz: 0.000000; ash T_Kantengeometrie: -; ash T_Kantenmaterial: -; ash T_Blatt_Oberfläche: -; ash T_Erford. Durgangshöhe: 0 m; ash T_Rammschutz: -; ash T_Fluchtwegrichtung: -; ash T_Anschlag Gangflügel: -; ash T_Bodendichtung: -; ash T_Lüftungsgitter: 0 m2; ash T_Feuchtebeständigkeit: -; ash T_E_Öffner: -; ash T_Automatik_Antrieb: -; ash T_Sturz: -; ash T_Blatt_Material: -; ash T_Schlossfunktion: -; ash T_Schliesszylinder: -; ash T_Beschlag: -; ash T_Material Oberlicht: -; ash T_Glasausschnitt: -; ash T_Sonder_Wandmaterial: -; ash T_Anz_Reedkontakte: 0; ash T_Anz_Riegelkontakte: 0; ash T_Schallschutz: -; ash T_Zarge_Material: -; ash T_Bodeneinstand: -; ash T_Raum zugehörigkeit: BS; ash T_Blatt_Farbe: -; Positionsnummer_Text: U23; Attributset-Objekt: Door; Abrechnungsart: St
AllplanQuantities - GlassSurface: 2.1146; HeightWindowSillOutside: 0; HeightWindowSillInside: 0; OffsetOpeningBottom: 200; OffsetOpeningTop: 0; OffsetOpeningLeft: 0; OffsetOpeningRight: 0; DeductionOpeningBottom: 150; DeductionOpeningLeft: 50; DeductionOpeningRight: 50; DeductionOpeningTop: 50
Pset_DoorCommon - Status: NEW; IsExternal: yes; FireRating: 0; ThermalTransmittance: 1 W/K/m2; AcousticRating: -; SecurityRating: RC 1; Reference: T_Typ16
Name | Text1 | ash T_Tür-Nr. | g-Wert | P_ID | Allright_Bauteil_ID
SMT | 4 | TA-1FL-D-E00-L005 | ,51 | 1115Rau0000005119 | 1105Mak0000085526
SMT | 10 | TA-1FL-D-E00-L003 | 0,35 | 1115Rau0000005223 | 1105Mak0000085645

# IfcDoor: SMT (12)
Type - PredefinedType: DOOR; OperationType: SINGLE_SWING_RIGHT; ParameterTakesPrecedence: no
Type - IfcDoorLiningProperties - LiningDepth: 0.22 m; LiningThickness: 0.04 m
OverallWidth: 1.26 m
AllplanAttributes (SMT) - Gewerk: Metallbau-, Schlosserarbeiten; V6: 0 m; V7: 0 m; V8: 0 m; V9: 0; Programmversion: 3.1; Objektname: Türmakro; Bezeichnung: SMT; Plugin_Bezeichnung: MainObject; Plugin_Objektname: SmartPartCompressed; Glasanteil_berücksichtigen: 100; Version: 7.21; ash T_Sichtschutz: -; ash R_Verweis Wandansicht: -; ash T_Zulage Schachttür: no; ash T_Dichtschließend: no; ash T_Panik: -; ash T_Zarge_Typ: UZ; ash T_Türschließer: -; ash T_Gewerk Los: -; ash T_Erforderl. Durchgangsbreite: 0 m; ash T_Türblatt sichtbar 2D: ja; ash T_Zusatzfunktion Panikschloss: -; ash T_Fluchtwegsicherung: -; ash T_Standflügel-Betätigung: -; ash T_Zusatzfunktion Türschließer: -; ash T_Türschließer-Montage: -; ash T_Feststellanlage (FSA): -; ash T_Zusätzliche Rauchmelder: -; ash T_Zusätzl. Anschluss an BMA: -; ash T_Impulsgeber: -; ash T_Sicherheits-Sensorleisten: -; ash T_Anschl. an Einbruchmeld.anl.: -; ash T_Klemmschutz: -; ash T_LV-Positions-Nr.: -; ash T_Plan-Nr.: -; ash T_Sonstiges, Bemerkungen: -; ash T_Bodentürstopper: -; ash T_nicht abschließbar: no; ash T_Material Seitenteil: -; ash T_Kantengeometrie: 2F; ash T_Kantenmaterial: PU; ash T_Blatt_Oberfläche: HPL; ash T_Erford. Durgangshöhe: 0 m; ash T_Rammschutz: BL; ash T_Fluchtwegrichtung: -; ash T_Bodendichtung: Ja; ash T_Lüftungsgitter: 0 m2; ash T_Feuchtebeständigkeit: -; ash T_E_Öffner: -; ash T_Automatik_Antrieb: -; ash T_Sturz: -; ash T_Blatt_Material: HO; ash T_Schlossfunktion: -; ash T_Schliesszylinder: PZ; ash T_Beschlag: DD; ash T_Glasausschnitt: -; ash T_Sonder_Wandmaterial: -; ash T_Anz_Riegelkontakte: 0; ash T_Zarge_Material: ST; ash T_Bodeneinstand: -; ash T_Raum zugehörigkeit: BGS; ash T_Blatt_Farbe: -; Attributset-Objekt: Door; Abrechnungsart: St
AllplanAttributes (TGR 1.6) - Codetext: Typ; V6: 0 m; V7: 0 m; V8: 0 m; V9: 0; Programmversion: 3.1; Objektname: TGR-Makro; Text1: PlanNo.; Bezeichnung: TGR 1.6; Plugin_Bezeichnung: MainObject; Plugin_Objektname: SmartPartCompressed; Version: 1.6; ash T_Türprofilnummer: 3; Abrechnungsart: St
AllplanQuantities - GlassSurface: 0; HeightWindowSillOutside: 0; HeightWindowSillInside: 0; OffsetOpeningTop: 0; OffsetOpeningLeft: 0; OffsetOpeningRight: 0; DeductionOpeningBottom: 100; DeductionOpeningLeft: 40; DeductionOpeningRight: 40; DeductionOpeningTop: 40
Pset_DoorCommon - Status: NEW; IsExternal: no; ThermalTransmittance: 0 W/K/m2; HandicapAccessible: no; SmokeStop: no; SelfClosing: no; FireExit: no
Name | In | OverallHeight (m) | Material = AllplanAttributes (SMT), Material | AllplanAttributes (SMT), Ortscode_Geschoßbezeichnung | Text1 | AllplanAttributes (SMT), OKFF | ash T_Tür-Nr. | ash T_Anz_Reedkontakte | ash T_Schallschutz | P_ID | AllplanAttributes (SMT), Allright_Bauteil_ID | Gesamtlänge | AllplanAttributes (TGR 1.6), OKFF | AllplanAttributes (TGR 1.6), Allright_Bauteil_ID | OffsetOpeningBottom | ash T_Strahlenschutz | ash T_Anschlag Gangflügel | AllplanAttributes (SMT), Positionsnummer_Text = AllplanAttributes (TGR 1.6), Positionsnummer_Text
SMT | H2 Ebene +2 | 2.41 | TI-1F-UZ-D | E02 | 75 | 7.5 | E02-004-001-75 | 1 | 32 dB | 1215Rau0000006920 | 1213Mak0813004504 | 8.36 | 7.5 | 1213Mak0813223858 | 150 | AllplanAttributes (SMT) - ash T_Steuerung (BS): I; AllplanAttributes (TGR 1.6) - Ortscode_Geschoßbezeichnung: E02
SMT | H2 Ebene +2 | 2.41 | TI-1F-UZ-D | E02 | 74 | 7.5 | E02-005-001-74 | 0 | 32 dB | 1215Rau0000006920 | 1213Mak0813004509 | 8.36 | 7.5 | 1213Mak0813223841 | 150 | AllplanAttributes (TGR 1.6) - Ortscode_Geschoßbezeichnung: E02
SMT | H2 Ebene +2 | 2.41 | TI-1F-UZ-D | E02 | 100 | 7.5 | E02-059-001-100 | 1 | 32 dB | 1215Rau0000006941 | 1213Mak0813004239 | 8.36 | 7.5 | 1213Mak0813224000 | 150 | AllplanAttributes (SMT) - ash T_Steuerung (BS): I; AllplanAttributes (TGR 1.6) - Ortscode_Geschoßbezeichnung: E02
SMT | H2 Ebene +2 | 2.41 | TI-1F-UZ-D | E02 | 101 | 7.5 | E02-058-001-101 | 0 | 32 dB | 1215Rau0000006941 | 1213Mak0813004234 | 8.36 | 7.5 | 1213Mak0813223997 | 150 | AllplanAttributes (TGR 1.6) - Ortscode_Geschoßbezeichnung: E02
SMT | H2 Ebene +1 | 2.41 | TI-1F-UZ-D | E01 | 74 | 3.75 | E01-005-001-74 | 0 | 32 dB | 1165Rau0000004808 | 1163Mak0812516234 | 8.36 |  | 1163Mak0814151898 | 150 | 0.000000 | - | U100
SMT | H2 Ebene +1 | 2.41 | TI-1F-UZ-D | E01 | 100 | 3.75 | E01-059-001-100 | 1 | 32 dB | 1165Rau0000004819 | 1163Mak0812438670 | 8.36 |  | 1163Mak0814151648 | 150 | 0.000000 | - | U100 | AllplanAttributes (SMT) - ash T_Steuerung (BS): I
SMT | H2 Ebene +1 | 2.41 | TI-1F-UZ-ZK | E01 | 101 | 3.75 | E01-058-001-101 | 0 | 32 dB | 1165Rau0000004819 | 1163Mak0812524521 | 8.36 |  | 1163Mak0814151651 | 150 | 0.000000 | - | U100
SMT | H2 Ebene +1 | 2.41 | TI-1F-UZ-D | E01 | 75 | 3.75 | E01-004-001-75 | 1 | 32 dB | 1165Rau0000004808 | 1163Mak0812435722 | 8.36 |  | 1163Mak0814180295 | 150 | 0.000000 | - | U100 | AllplanAttributes (SMT) - ash T_Steuerung (BS): I; ash T_Laserschutz: -
SMT | H2 Ebene 0 | 2.46 | TI-1F-UZ-D | E00 | 75 | 0 | E00-004-001-75 | 1 | 32 dB | 1115Rau0000005181 | 1113Mak0812435722 | 8.46 | 0 | 1113Mak0813548127 | 200 | 0.000000 | - | S68 | AllplanAttributes (SMT) - ash T_Steuerung (BS): I
SMT | H2 Ebene 0 | 2.46 | TI-1F-UZ-D | E00 | 74 | 0 | E00-005-001-74 | 0 | 32 | 1115Rau0000005181 | 1113Mak0812516234 | 8.46 | 0 | 1113Mak0813548622 | 200 | 0.000000 | - | S68
SMT | H2 Ebene 0 | 2.46 | TI-1F-UZ-D | E00 | 100 | 0 | E00-059-001-100 | 1 | 32 dB | 1115Rau0000005220 | 1113Mak0812438670 | 8.46 | 0 | 1113Mak0813547701 | 200 | 0.000000 | - | S68 | AllplanAttributes (SMT) - ash T_Steuerung (BS): I
SMT | H2 Ebene 0 | 2.46 | TI-1F-UZ-ZK | E00 | 101 | 0 | E00-058-001-101 | 0 | 32 | 1115Rau0000005220 | 1113Mak0812524521 | 8.46 | 0 | 1113Mak0813547698 | 200 | 0.000000 | - | S68

# IfcDoor: SMT (21)
Type - PredefinedType: DOOR; OperationType: SINGLE_SWING_RIGHT; ParameterTakesPrecedence: no
Type - IfcDoorLiningProperties - LiningDepth: 0.262 m; LiningThickness: 0.04 m
AllplanAttributes (SMT) - V6: 0 m; V7: 0 m; V8: 0 m; V9: 0; Objektname: Türmakro; Bezeichnung: SMT; Plugin_Bezeichnung: MainObject; Plugin_Objektname: SmartPartCompressed; Glasanteil_berücksichtigen: 100; ash T_Zulage Schachttür: no; ash T_Zarge_Typ: UZ; ash T_Erforderl. Durchgangsbreite: 0 m; ash T_Türblatt sichtbar 2D: ja; ash T_nicht abschließbar: no; ash T_Erford. Durgangshöhe: 0 m; ash T_Lüftungsgitter: 0 m2; ash T_Anz_Reedkontakte: 0; ash T_Anz_Riegelkontakte: 0; ash T_Schallschutz: -; ash T_Zarge_Material: ST; Attributset-Objekt: Door; Abrechnungsart: St
AllplanQuantities - GlassSurface: 0; HeightWindowSillOutside: 0; HeightWindowSillInside: 0; OffsetOpeningTop: 0; OffsetOpeningLeft: 0; OffsetOpeningRight: 0; DeductionOpeningBottom: 100; DeductionOpeningLeft: 40; DeductionOpeningRight: 40; DeductionOpeningTop: 40
Pset_DoorCommon - Status: NEW; IsExternal: no; ThermalTransmittance: 0 W/K/m2; HandicapAccessible: no; FireExit: no
Name | In | OverallHeight (m) | OverallWidth (m) | Material = AllplanAttributes (SMT), Material | Gewerk | Ortscode_Geschoßbezeichnung | Programmversion | Text1 | Version | ash T_Dichtschließend | ash T_Türschließer | OKFF | ash T_Strahlenschutz | ash T_Tür-Nr. | ash T_Kantengeometrie | ash T_Blatt_Oberfläche | ash T_Anschlag Gangflügel | ash T_Blatt_Material | ash T_Schliesszylinder | ash T_Beschlag | ash T_Raum zugehörigkeit | P_ID | Allright_Bauteil_ID | OffsetOpeningBottom | SmokeStop = SelfClosing | ash T_Sichtschutz = ash R_Verweis Wandansicht = ash T_Panik = ash T_Gewerk Los = ash T_Zusatzfunktion Panikschloss = ash T_Fluchtwegsicherung = ash T_Standflügel-Betätigung = ash T_Zusatzfunktion Türschließer = ash T_Türschließer-Montage = ash T_Zusätzliche Rauchmelder = ash T_Zusätzl. Anschluss an BMA = ash T_Impulsgeber = ash T_Sicherheits-Sensorleisten = ash T_Anschl. an Einbruchmeld.anl. = ash T_Klemmschutz = ash T_LV-Positions-Nr. = ash T_Plan-Nr. = ash T_Sonstiges, Bemerkungen = ash T_Bodentürstopper = ash T_Material Seitenteil = ash T_Fluchtwegrichtung = ash T_Bodendichtung = ash T_E_Öffner = ash T_Automatik_Antrieb = ash T_Sturz = ash T_Schlossfunktion = ash T_Glasausschnitt = ash T_Sonder_Wandmaterial = ash T_Bodeneinstand = ash T_Blatt_Farbe | ash T_Feststellanlage (FSA) | ash T_Kantenmaterial | ash T_Rammschutz | ash T_Feuchtebeständigkeit | Positionsnummer_Text
SMT | H2 Ebene +3 | 2.41 | 1.01 | TI-1F-UZ-D | Metallbau-, Schlosserarbeiten | E03 | 3.0 | 26 | 8.11 | no | OTS | 11.25 | 0.000000 | E03-011-001-26 | LF | L | - | ST | PZ | DK | BS | 1266Rau0000012840 | 1263Mak0812598134 | 150 | yes | AllplanAttributes (SMT) - Text2: -; Pset_DoorCommon - FireRating: EI2 30
SMT | H2 Ebene +3 | 2.41 | 1.385 | TI-1F-UZ-D | Metallbau-, Schlosserarbeiten | E03 | 3.1 | 6 | 7.21 | no | OTS | 11.25 | 0.000000 | E03-003-001-6 | LF | L | - | ST | PZ | KD | BGS | 1265Rau0000000034 | 1263Mak0812546794 | 150 | yes | AllplanAttributes (SMT) - Text2: -; Pset_DoorCommon - FireRating: EI2 30
SMT | H2 Ebene +2 | 2.41 | 0.885 | TI-1F-UZ-D | Metallbau-, Schlosserarbeiten | E02 | 3.1 | 46 | 7.21 | yes | - | 7.5 |  | E02-030-001-46 | 2F | HPL |  | HO | Kn-PZ | KD | BGS | 1215Rau0000006929 | 1213Mak0813004760 | 150 | no | - | - | PU | BL | -
SMT | H2 Ebene +2 | 2.41 | 0.885 | TI-1F-UZ-D | Metallbau-, Schlosserarbeiten | E02 | 3.1 | 47 | 7.21 | yes | - | 7.5 |  | E02-031-001-47 | 2F | HPL |  | HO | Kn-PZ | KD | BGS | 1215Rau0000006929 | 1213Mak0813004754 | 150 | no | - | - | PU | BL | F
SMT | H2 Ebene +2 | 2.41 | 1.01 | TI-1F-UZ-D | Zimmer- und Holzbauarbeiten | E02 | 3.1 | 120 | 7.21 | no | OTS | 7.5 | 0.000000 | E00-075-001-120 | 2F | HPL | - | HO | PZ | KD | BGS | 1215Rau0000006899 | 1213Mak0813240532 | 150 | yes | - | - | PU | BL | - | Pset_DoorCommon - FireRating: EI2 30
SMT | H2 Ebene +2 | 2.41 | 0.885 | TI-1F-UZ-D | Metallbau-, Schlosserarbeiten | E02 | 3.1 | 128 | 7.21 | yes | - | 7.5 |  | E02-080-001-128 | 2F | HPL |  | HO | Kn-PZ | KD | BGS | 1215Rau0000006932 | 1213Mak0813004365 | 150 | no | - | - | PU | BL | F
SMT | H2 Ebene +2 | 2.41 | 0.885 | TI-1F-UZ-D | Metallbau-, Schlosserarbeiten | E02 | 3.1 | 127 | 7.21 | yes | - | 7.5 |  | E02-079-001-127 | 2F | HPL |  | HO | Kn-PZ | KD | BGS | 1215Rau0000006932 | 1213Mak0813004359 | 150 | no | - | - | PU | BL | F
SMT | H2 Ebene +2 | 2.41 | 1.26 | TI-1F-UZ-D | Metallbau-, Schlosserarbeiten | E02 | 3.1 | 87 | 7.21 | no | - | 7.5 |  | E02-F08-002-87 | 2F | HPL | - | HO | PZ | KD | BS | 1215Rau0000006905 | 1213Mak0813004163 | 150 | yes | - | FL | PU | BL | - | Pset_DoorCommon - FireRating: EI2 30
SMT | H2 Ebene +2 | 2.41 | 1.01 | TI-1F-UZ-D | Zimmer- und Holzbauarbeiten | E02 | 3.1 | 54 | 7.21 | no | OTS | 7.5 |  | E02-040-001-54 | 2F | HPL |  | HO | PZ | KD | BGS | 1215Rau0000006899 | 1213Mak0813004721 | 150 | yes | - | - | PU | BL | - | Pset_DoorCommon - FireRating: EI2 30
SMT | H2 Ebene +1 | 2.41 | 0.885 | TI-1F-UZ-D-N | Metallbau-, Schlosserarbeiten | E01 | 3.1 | 47 | 7.21 | yes | - | 3.75 | 0.000000 | E01-031-001-47 | 2F | HPL | - | HO | Kn-PZ | KD | BGS | 1165Rau0000004677 | 1163Mak0812443591 | 150 | no | - | - | PU | BL | F | U100
SMT | H2 Ebene +1 | 2.41 | 0.885 | TI-1F-UZ-D-N | Metallbau-, Schlosserarbeiten | E01 | 3.1 | 46 | 7.21 | yes | - | 3.75 | 0.000000 | E01-030-001-46 | 2F | HPL | - | HO | Kn-PZ | KD | BGS | 1165Rau0000004677 | 1163Mak0812443595 | 150 | no | - | - | PU | BL | - | U100
SMT | H2 Ebene +1 | 2.41 | 1.01 | TI-1F-UZ-ZK | Zimmer- und Holzbauarbeiten | E01 | 3.1 | 120 | 7.21 | no | OTS | 3.75 | 0.000000 | E01-075-001-120 | 2F | HPL | - | HO | PZ | KD | BGS | 1165Rau0000004712 | 1163Mak0812436303 | 150 | yes | - | - | PU | BL | - | U100 | Pset_DoorCommon - FireRating: EI2 30
SMT | H2 Ebene +1 | 2.41 | 0.885 | TI-1F-UZ-D-N | Metallbau-, Schlosserarbeiten | E01 | 3.1 | 128 | 7.21 | yes | - | 3.75 | 0.000000 | E01-080-001-128 | 2F | HPL | - | HO | Kn-PZ | KD | BGS | 1165Rau0000004725 | 1163Mak0812655404 | 150 | no | - | - | PU | BL | F | U100
SMT | H2 Ebene +1 | 2.41 | 0.885 | TI-1F-UZ-D-N | Metallbau-, Schlosserarbeiten | E01 | 3.1 | 127 | 7.21 | yes | - | 3.75 | 0.000000 | E01-079-001-127 | 2F | HPL | - | HO | Kn-PZ | KD | BGS | 1165Rau0000004725 | 1163Mak0812655402 | 150 | no | - | - | PU | BL | F | U100
SMT | H2 Ebene +1 | 2.41 | 1.01 | TI-1F-UZ-ZK | Zimmer- und Holzbauarbeiten | E01 | 3.1 | 54 | 7.21 | no | OTS | 3.75 | 0.000000 | E01-040-001-54 | 2F | HPL | - | HO | PZ | KD | BGS | 1165Rau0000004688 | 1163Mak0812440817 | 150 | yes | - | - | PU | BL | - | U100 | Pset_DoorCommon - FireRating: EI2 30; AllplanAttributes (SMT) - ash T_Laserschutz: -
SMT | H2 Ebene 0 | 2.46 | 1.01 | TI-1F-UZ-ZK | Zimmer- und Holzbauarbeiten | E00 | 3.1 | 120 | 7.21 | no | OTS | 0 | 0.000000 | E00-075-001-120 | 2F | HPL | - | HO | PZ | KD | BGS | 1115Rau0000005223 | 1113Mak0812436303 | 200 | yes | - | - | PU | BL | - | S68 | Pset_DoorCommon - FireRating: EI2 30
SMT | H2 Ebene 0 | 2.46 | 0.885 | TI-1F-UZ-D-N | Metallbau-, Schlosserarbeiten | E00 | 3.1 | 127 | 7.21 | yes | - | 0 | 0.000000 | E00-079-001-127 | 2F | HPL | - | HO | Kn-PZ | KD | BGS | 1115Rau0000005072 | 1113Mak0812655402 | 200 | no | - | - | PU | BL | F | S68
SMT | H2 Ebene 0 | 2.46 | 0.885 | TI-1F-UZ-D-N | Metallbau-, Schlosserarbeiten | E00 | 3.1 | 128 | 7.21 | yes | - | 0 | 0.000000 | E00-080-001-128 | 2F | HPL | - | HO | Kn-PZ | KD | BGS | 1115Rau0000005072 | 1113Mak0812655404 | 200 | no | - | - | PU | BL | F | S68
SMT | H2 Ebene 0 | 2.46 | 1.01 | TI-1F-UZ-ZK | Zimmer- und Holzbauarbeiten | E00 | 3.1 | 54 | 7.21 | no | OTS | 0 | 0.000000 | E00-040-001-54 | 2F | HPL | - | HO | PZ | KD | BGS | 1115Rau0000005169 | 1113Mak0812440817 | 200 | yes | - | - | PU | BL | - | S68 | Pset_DoorCommon - FireRating: EI2 30
SMT | H2 Ebene 0 | 2.46 | 0.885 | TI-1F-UZ-D-N | Metallbau-, Schlosserarbeiten | E00 | 3.1 | 46 | 7.21 | yes | - | 0 | 0.000000 | E00-030-001-46 | 2F | HPL | - | HO | Kn-PZ | KD | BGS | 1115Rau0000005065 | 1113Mak0812443595 | 200 | no | - | - | PU | BL | - | S68
SMT | H2 Ebene 0 | 2.46 | 0.885 | TI-1F-UZ-D-N | Metallbau-, Schlosserarbeiten | E00 | 3.1 | 47 | 7.21 | yes | - | 0 | 0.000000 | E00-031-001-47 | 2F | HPL | - | HO | Kn-PZ | KD | BGS | 1115Rau0000005065 | 1113Mak0812443591 | 200 | no | - | - | PU | BL | F | S68

# IfcDoor: SMT (8)
Type - PredefinedType: DOOR; OperationType: SINGLE_SWING_RIGHT; ParameterTakesPrecedence: no
Type - IfcDoorLiningProperties - LiningDepth: 0.28 m; LiningThickness: 0.04 m
AllplanAttributes (SMT) - V6: 0 m; V7: 0 m; V8: 0 m; V9: 0; Programmversion: 3.1; Objektname: Türmakro; Bezeichnung: SMT; Plugin_Bezeichnung: MainObject; Plugin_Objektname: SmartPartCompressed; Glasanteil_berücksichtigen: 100; Version: 7.21; ash T_Zulage Schachttür: no; ash T_Dichtschließend: no; ash T_Zarge_Typ: UZ; ash T_Türschließer: OTS; ash T_Erforderl. Durchgangsbreite: 0 m; ash T_Türblatt sichtbar 2D: ja; ash T_nicht abschließbar: no; ash T_Erford. Durgangshöhe: 0 m; ash T_Anschlag Gangflügel: -; ash T_Lüftungsgitter: 0 m2; ash T_Schliesszylinder: PZ; ash T_Beschlag: KD; ash T_Anz_Reedkontakte: 0; ash T_Anz_Riegelkontakte: 0; ash T_Schallschutz: -; ash T_Zarge_Material: ST; Attributset-Objekt: Door; Abrechnungsart: St
AllplanQuantities - GlassSurface: 0; HeightWindowSillOutside: 0; HeightWindowSillInside: 0; OffsetOpeningTop: 0; OffsetOpeningLeft: 0; OffsetOpeningRight: 0; DeductionOpeningBottom: 100; DeductionOpeningLeft: 40; DeductionOpeningRight: 40; DeductionOpeningTop: 40
Pset_DoorCommon - Status: NEW; IsExternal: no; FireRating: EI2 30; ThermalTransmittance: 0 W/K/m2; HandicapAccessible: no; SmokeStop: yes; SelfClosing: yes; FireExit: no
Name | In | OverallHeight (m) | OverallWidth (m) | Material = AllplanAttributes (SMT), Material | Gewerk | Ortscode_Geschoßbezeichnung | Text1 | OKFF | ash T_Strahlenschutz | ash T_Tür-Nr. | ash T_Kantengeometrie | ash T_Blatt_Oberfläche | ash T_Blatt_Material | ash T_Raum zugehörigkeit | P_ID | Allright_Bauteil_ID | OffsetOpeningBottom | ash T_Feststellanlage (FSA) | ash T_Sichtschutz = ash R_Verweis Wandansicht = ash T_Panik = ash T_Gewerk Los = ash T_Zusatzfunktion Panikschloss = ash T_Fluchtwegsicherung = ash T_Standflügel-Betätigung = ash T_Zusatzfunktion Türschließer = ash T_Türschließer-Montage = ash T_Zusätzliche Rauchmelder = ash T_Zusätzl. Anschluss an BMA = ash T_Impulsgeber = ash T_Sicherheits-Sensorleisten = ash T_Anschl. an Einbruchmeld.anl. = ash T_Klemmschutz = ash T_LV-Positions-Nr. = ash T_Plan-Nr. = ash T_Sonstiges, Bemerkungen = ash T_Bodentürstopper = ash T_Material Seitenteil = ash T_Fluchtwegrichtung = ash T_Bodendichtung = ash T_Feuchtebeständigkeit = ash T_E_Öffner = ash T_Automatik_Antrieb = ash T_Sturz = ash T_Schlossfunktion = ash T_Glasausschnitt = ash T_Sonder_Wandmaterial = ash T_Bodeneinstand = ash T_Blatt_Farbe | ash T_Kantenmaterial | ash T_Rammschutz
SMT | H2 Ebene +3 | 2.41 | 1.01 | TI-1F-UZ-D | Metallbau-, Schlosserarbeiten | E03 | 32 | 11.25 | 0.000000 | E03-016-001-32 | LF | L | ST | BGS | 1265Rau0000000005 | 1263Mak0812547705 | 150 | AllplanAttributes (SMT) - Text2: -
SMT | H2 Ebene +3 | 2.41 | 0.76 | TI-1F-UZ-D | Metallbau-, Schlosserarbeiten | E03 | 4 | 11.25 | 0.000000 | E03-S01-001-4 | LF | L | ST | BGS | 1266Rau0000012858 | 1263Mak0813064810 | 150 | - | AllplanAttributes (SMT) - Text2: -
SMT | H2 Ebene +2 | 2.41 | 0.885 | TI-1F-UZ-D | Zimmer- und Holzbauarbeiten | E02 | 89 | 7.5 |  | E02-054-001-89 | 2F | HPL | HO | BGS | 1215Rau0000006923 | 1213Mak0813004151 | 150 | - | - | PU | BL
SMT | H2 Ebene +2 | 2.41 | 0.885 | TI-1F-UZ-D | Zimmer- und Holzbauarbeiten | E02 | 90 | 7.5 |  | E02-053-001-90 | 2F | HPL | HO | BGS | 1215Rau0000006923 | 1213Mak0813004099 | 150 | - | - | PU | BL
SMT | H2 Ebene +1 | 2.41 | 0.885 | TI-1F-UZ-ZK | Zimmer- und Holzbauarbeiten | E01 | 89 | 3.75 | 0.000000 | E01-054-001-89 | 2F | HPL | HO | BS | 1165Rau0000004771 | 1163Mak0812436831 | 150 | - | - | PU | BL | AllplanAttributes (SMT) - Positionsnummer_Text: U100
SMT | H2 Ebene +1 | 2.41 | 0.885 | TI-1F-UZ-ZK | Zimmer- und Holzbauarbeiten | E01 | 90 | 3.75 | 0.000000 | E01-053-001-90 | 2F | HPL | HO | BS | 1165Rau0000004771 | 1163Mak0812436835 | 150 | - | - | PU | BL | AllplanAttributes (SMT) - Positionsnummer_Text: U100
SMT | H2 Ebene 0 | 2.46 | 0.885 | TI-1F-UZ-ZK | Zimmer- und Holzbauarbeiten | E00 | 89 | 0 | 0.000000 | E00-054-001-89 | 2F | HPL | HO | BGS | 1115Rau0000005075 | 1113Mak0812436831 | 200 | - | - | PU | BL | AllplanAttributes (SMT) - Positionsnummer_Text: S68
SMT | H2 Ebene 0 | 2.46 | 0.885 | TI-1F-UZ-ZK | Zimmer- und Holzbauarbeiten | E00 | 90 | 0 | 0.000000 | E00-053-001-90 | 2F | HPL | HO | BGS | 1115Rau0000005075 | 1113Mak0812436835 | 200 | - | - | PU | BL | AllplanAttributes (SMT) - Positionsnummer_Text: S68

# IfcDoor: SMT (3)
In: H2 Ebene 0
Type - PredefinedType: DOOR; OperationType: SINGLE_SWING_RIGHT; ParameterTakesPrecedence: no
Type - IfcDoorLiningProperties - LiningDepth: 0.301 m; LiningThickness: 0.04 m
OverallHeight: 2.46 m; OverallWidth: 1.01 m; Material: TI-1F-UZ-ZK
AllplanAttributes (SMT) - Gewerk: Zimmer- und Holzbauarbeiten; V6: 0 m; V7: 0 m; V8: 0 m; V9: 0; Ortscode_Geschoßbezeichnung: E00; Programmversion: 3.1; Objektname: Türmakro; Bezeichnung: SMT; Material: TI-1F-UZ-ZK; Plugin_Bezeichnung: MainObject; Plugin_Objektname: SmartPartCompressed; Glasanteil_berücksichtigen: 100; Version: 7.21; ash T_Sichtschutz: -; ash R_Verweis Wandansicht: -; ash T_Zulage Schachttür: no; ash T_Dichtschließend: yes; ash T_Panik: -; ash T_Zarge_Typ: UZ; ash T_Türschließer: -; ash T_Gewerk Los: -; ash T_Erforderl. Durchgangsbreite: 0 m; ash T_Türblatt sichtbar 2D: ja; ash T_Zusatzfunktion Panikschloss: -; ash T_Fluchtwegsicherung: -; ash T_Standflügel-Betätigung: -; ash T_Zusatzfunktion Türschließer: -; ash T_Türschließer-Montage: -; ash T_Feststellanlage (FSA): -; ash T_Zusätzliche Rauchmelder: -; ash T_Zusätzl. Anschluss an BMA: -; ash T_Impulsgeber: -; ash T_Sicherheits-Sensorleisten: -; ash T_Anschl. an Einbruchmeld.anl.: -; ash T_Klemmschutz: -; ash T_LV-Positions-Nr.: -; ash T_Plan-Nr.: -; ash T_Sonstiges, Bemerkungen: -; OKFF: 0; ash T_nicht abschließbar: no; ash T_Material Seitenteil: -; ash T_Strahlenschutz: 0.000000; ash T_Kantengeometrie: 2F; ash T_Kantenmaterial: PU; ash T_Blatt_Oberfläche: HPL; ash T_Erford. Durgangshöhe: 0 m; ash T_Rammschutz: BL; ash T_Fluchtwegrichtung: -; ash T_Anschlag Gangflügel: -; ash T_Bodendichtung: Ja; ash T_Lüftungsgitter: 0 m2; ash T_Feuchtebeständigkeit: -; ash T_E_Öffner: -; ash T_Automatik_Antrieb: -; ash T_Sturz: -; ash T_Blatt_Material: HO; ash T_Schlossfunktion: -; ash T_Schliesszylinder: PZ; ash T_Beschlag: DK; ash T_Glasausschnitt: -; ash T_Sonder_Wandmaterial: -; ash T_Anz_Reedkontakte: 0; ash T_Anz_Riegelkontakte: 0; ash T_Zarge_Material: ST; ash T_Bodeneinstand: -; ash T_Raum zugehörigkeit: BS; ash T_Blatt_Farbe: -; Positionsnummer_Text: S68; Attributset-Objekt: Door; Abrechnungsart: St
AllplanQuantities - GlassSurface: 0; HeightWindowSillOutside: 0; HeightWindowSillInside: 0; OffsetOpeningBottom: 200; OffsetOpeningTop: 0; OffsetOpeningLeft: 0; OffsetOpeningRight: 0; DeductionOpeningBottom: 100; DeductionOpeningLeft: 40; DeductionOpeningRight: 40; DeductionOpeningTop: 40
Pset_DoorCommon - Status: NEW; IsExternal: no; ThermalTransmittance: 0 W/K/m2; HandicapAccessible: no; SmokeStop: no; SelfClosing: no; FireExit: no
Name | Text1 | ash T_Bodentürstopper | ash T_Tür-Nr. | ash T_Schallschutz | P_ID | Allright_Bauteil_ID
SMT | 42 | - | E00-036-001-42 | 27 dB | 1116Rau0000066684 | 1113Mak0812443195
SMT | 45 | - | E00-035-001-45 | 27 dB | 1116Rau0000066687 | 1113Mak0813518668
SMT | 79 | W | E00-009-001-79 | - | 1116Rau0000066535 | 1113Mak0812446814 | Pset_DoorCommon - FireRating: -

# IfcDoor: SMT (3)
Type - PredefinedType: DOOR; OperationType: SINGLE_SWING_RIGHT; ParameterTakesPrecedence: no
Type - IfcDoorLiningProperties - LiningDepth: 0.302 m; LiningThickness: 0.04 m
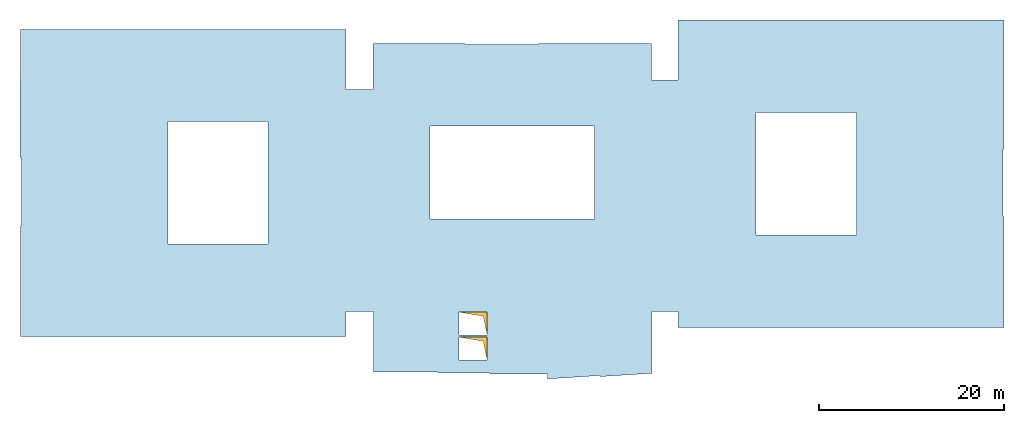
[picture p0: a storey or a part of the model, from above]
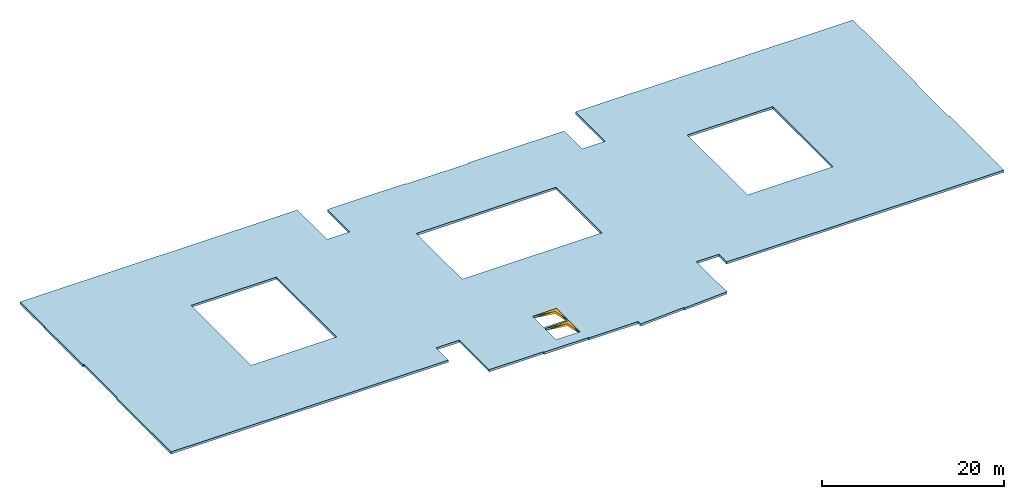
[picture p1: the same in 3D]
Properties of the parts of a building model (IFC4), part 27 of 80

# IfcDoor: SMT (3)
AllplanAttributes (SMT) - Gewerk: Zimmer- und Holzbauarbeiten; V6: 0 m; V7: 0 m; V8: 0 m; V9: 0; Programmversion: 3.1; Objektname: Türmakro; Bezeichnung: SMT; Plugin_Bezeichnung: MainObject; Plugin_Objektname: SmartPartCompressed; Glasanteil_berücksichtigen: 100; Version: 7.21; ash T_Sichtschutz: -; ash R_Verweis Wandansicht: -; ash T_Zulage Schachttür: no; ash T_Panik: -; ash T_Zarge_Typ: UZ; ash T_Gewerk Los: -; ash T_Erforderl. Durchgangsbreite: 0 m; ash T_Türblatt sichtbar 2D: ja; ash T_Zusatzfunktion Panikschloss: -; ash T_Fluchtwegsicherung: -; ash T_Standflügel-Betätigung: -; ash T_Zusatzfunktion Türschließer: -; ash T_Türschließer-Montage: -; ash T_Feststellanlage (FSA): -; ash T_Zusätzliche Rauchmelder: -; ash T_Zusätzl. Anschluss an BMA: -; ash T_Impulsgeber: -; ash T_Sicherheits-Sensorleisten: -; ash T_Anschl. an Einbruchmeld.anl.: -; ash T_Klemmschutz: -; ash T_LV-Positions-Nr.: -; ash T_Plan-Nr.: -; ash T_Sonstiges, Bemerkungen: -; ash T_nicht abschließbar: no; ash T_Material Seitenteil: -; ash T_Strahlenschutz: 0.000000; ash T_Kantengeometrie: 2F; ash T_Kantenmaterial: PU; ash T_Blatt_Oberfläche: HPL; ash T_Erford. Durgangshöhe: 0 m; ash T_Rammschutz: BL; ash T_Fluchtwegrichtung: -; ash T_Anschlag Gangflügel: -; ash T_Bodendichtung: Ja; ash T_Lüftungsgitter: 0 m2; ash T_Feuchtebeständigkeit: -; ash T_E_Öffner: -; ash T_Automatik_Antrieb: -; ash T_Sturz: -; ash T_Blatt_Material: HO; ash T_Schlossfunktion: -; ash T_Schliesszylinder: PZ; ash T_Glasausschnitt: -; ash T_Sonder_Wandmaterial: -; ash T_Anz_Reedkontakte: 0; ash T_Anz_Riegelkontakte: 0; ash T_Schallschutz: -; ash T_Zarge_Material: ST; ash T_Bodeneinstand: -; ash T_Raum zugehörigkeit: BS; ash T_Blatt_Farbe: -; Attributset-Objekt: Door; Abrechnungsart: St
AllplanQuantities - GlassSurface: 0; HeightWindowSillOutside: 0; HeightWindowSillInside: 0; OffsetOpeningTop: 0; OffsetOpeningLeft: 0; OffsetOpeningRight: 0; DeductionOpeningBottom: 100; DeductionOpeningLeft: 40; DeductionOpeningRight: 40; DeductionOpeningTop: 40
Pset_DoorCommon - Status: NEW; IsExternal: no; ThermalTransmittance: 0 W/K/m2; HandicapAccessible: no; FireExit: no
Name | In | OverallHeight (m) | OverallWidth (m) | Material = AllplanAttributes (SMT), Material | Ortscode_Geschoßbezeichnung | Text1 | ash T_Dichtschließend | ash T_Türschließer | OKFF | ash T_Bodentürstopper | ash T_Tür-Nr. | ash T_Beschlag | Positionsnummer_Text | P_ID | Allright_Bauteil_ID | OffsetOpeningBottom | FireRating | SmokeStop = SelfClosing
SMT | H2 Ebene +1 | 2.41 | 1.135 | TI-1F-UZ-D | E01 | 76 | no | OTS | 3.75 | - | E01-004-002-76 | DD | U100 | 1166Rau0000033131 | 1163Mak0812523051 | 150 | EI2 30 | yes
SMT | H2 Ebene +1 | 2.41 | 1.01 | TI-1F-UZ-ZK | E01 | 79 | yes | - | 3.75 | W | E01-009-001-79 | DK | U100 | 1166Rau0000033196 | 1163Mak0812446814 | 150 | - | no
SMT | H2 Ebene 0 | 2.46 | 1.135 | TI-1F-UZ-D | E00 | 76 | no | OTS | 0 | - | E00-004-002-76 | DD | S68 | 1116Rau0000066414 | 1113Mak0812523051 | 200 | EI2 30 | yes

# IfcDoor: SMT (6)
Type - PredefinedType: DOOR; OperationType: SINGLE_SWING_RIGHT; ParameterTakesPrecedence: no
Type - IfcDoorLiningProperties - LiningDepth: 0.304 m; LiningThickness: 0.04 m
AllplanAttributes (SMT) - Gewerk: Zimmer- und Holzbauarbeiten; V6: 0 m; V7: 0 m; V8: 0 m; V9: 0; Programmversion: 3.1; Objektname: Türmakro; Bezeichnung: SMT; Plugin_Bezeichnung: MainObject; Plugin_Objektname: SmartPartCompressed; Glasanteil_berücksichtigen: 100; Version: 7.21; ash T_Sichtschutz: -; ash R_Verweis Wandansicht: -; ash T_Zulage Schachttür: no; ash T_Dichtschließend: no; ash T_Panik: -; ash T_Zarge_Typ: UZ; ash T_Gewerk Los: -; ash T_Erforderl. Durchgangsbreite: 0 m; ash T_Türblatt sichtbar 2D: ja; ash T_Zusatzfunktion Panikschloss: -; ash T_Fluchtwegsicherung: -; ash T_Standflügel-Betätigung: -; ash T_Zusatzfunktion Türschließer: -; ash T_Türschließer-Montage: -; ash T_Zusätzliche Rauchmelder: -; ash T_Zusätzl. Anschluss an BMA: -; ash T_Impulsgeber: -; ash T_Sicherheits-Sensorleisten: -; ash T_Anschl. an Zuttrittskontrolle: -; ash T_Anschl. an Einbruchmeld.anl.: -; ash T_Klemmschutz: -; ash T_LV-Positions-Nr.: -; ash T_Plan-Nr.: -; ash T_Sonstiges, Bemerkungen: -; ash T_Bodentürstopper: -; ash T_nicht abschließbar: no; ash T_Material Seitenteil: -; ash T_Kantengeometrie: 2F; ash T_Kantenmaterial: PU; ash T_Blatt_Oberfläche: HPL; ash T_Erford. Durgangshöhe: 0 m; ash T_Rammschutz: BL; ash T_Fluchtwegrichtung: -; ash T_Lüftungsgitter: 0 m2; ash T_Feuchtebeständigkeit: -; ash T_Automatik_Antrieb: -; ash T_Sturz: -; ash T_Blatt_Material: HO; ash T_Schliesszylinder: PZ; ash T_Sonder_Wandmaterial: -; ash T_Anz_Reedkontakte: 0; ash T_Zarge_Material: ST; ash T_Bodeneinstand: -; ash T_Blatt_Farbe: -; Attributset-Objekt: Door; Abrechnungsart: St
AllplanQuantities - GlassSurface: 0; HeightWindowSillOutside: 0; HeightWindowSillInside: 0; OffsetOpeningTop: 0; OffsetOpeningLeft: 0; OffsetOpeningRight: 0; DeductionOpeningBottom: 100; DeductionOpeningLeft: 40; DeductionOpeningRight: 40; DeductionOpeningTop: 40
Pset_DoorCommon - Status: NEW; IsExternal: no; ThermalTransmittance: 0 W/K/m2; HandicapAccessible: no; FireExit: no
Name | In | OverallHeight (m) | OverallWidth (m) | Material = AllplanAttributes (SMT), Material | Ortscode_Geschoßbezeichnung | Text1 | ash T_Türschließer | ash T_Feststellanlage (FSA) | OKFF | ash T_Strahlenschutz | ash T_Tür-Nr. | ash T_Anschlag Gangflügel | ash T_Bodendichtung | ash T_E_Öffner | ash T_Schlossfunktion | ash T_Beschlag | ash T_Glasausschnitt | ash T_Anz_Riegelkontakte | ash T_Schallschutz | ash T_Raum zugehörigkeit | P_ID | Allright_Bauteil_ID | OffsetOpeningBottom | FireRating | SmokeStop = SelfClosing
SMT | H2 Ebene +2 | 2.41 | 1.26 | TI-1F-UZ-D | E02 | 19 | OTS | - | 7.5 | 0.000000 | E02-001-001-19 | - | - | - | - | DK | - | 0 | - | BS | 1216Rau0000046729 | 1213Mak0813005052 | 150 | EI2 30 | yes
SMT | H2 Ebene +2 | 2.41 | 1.26 | TI-1F-UZ-D | E02 | 20 | OTS | - | 7.5 |  | E02-002-001-20 |  | - | - | - | DK | - | 0 | - | BS | 1215Rau0000006938 | 1213Mak0813005046 | 150 | EI2 30 | yes
SMT | H2 Ebene +2 | 2.41 | 1.01 | TI-1F-UZ-D | E02 | 21 | - | - | 7.5 | 0.000000 | E02-003-001-21 | - | Ja | - | - | KD | - | 0 | 27 dB | BGS | 1215Rau0000006920 | 1213Mak0813723095 | 150 |  | no
SMT | H2 Ebene +1 | 2.41 | 1.26 | TI-1F-UZ-M-ZK | E01 | 17 | OTS | EMF | 3.75 | 0.000000 | E01-F03-001-17 | - | - |  | E | DK | - | 1 | - | BS | 1165Rau0000004666 | 1163Mak0814787066 | 150 | EI2 30 | yes | AllplanAttributes (SMT) - ash T_Laserschutz: -; ash T_Steuerung (BG): E; ash T_Steuerung (BS): B, E; Positionsnummer_Text: U100; Pset_DoorCommon - SecurityRating: SA
SMT | H2 Ebene 0 | 2.46 | 1.01 | TI-1F-UZ-D | E00 | 21 | - | - | 0 | 0.000000 | E00-003-001-21 | - | Ja | - | - | KD | - | 0 | 27 dB | BGS | 1116Rau0000065705 | 1113Mak0812447346 | 200 |  | no | AllplanAttributes (SMT) - ash T_Laserschutz: -; Positionsnummer_Text: S68
SMT | H2 Ebene 0 | 2.46 | 1.26 | TI-1F-UZ-M-ZK | E00 | 17 | OTS | EMF | 0 | 0.000000 | E00-F02-001-17 | - | - |  | E | DK | 35x100 | 1 | - | BS | 1115Rau0000005163 | 1113Mak0814282836 | 200 | EI2 30 | yes | AllplanAttributes (SMT) - ash T_Laserschutz: -; ash T_Steuerung (BG): E; ash T_Steuerung (BS): E; Positionsnummer_Text: S68; Text3: Handauslösetaster; Pset_DoorCommon - SecurityRating: SA

# IfcDoor: SMT (2)
In: H2 Ebene +1
Type - PredefinedType: DOOR; OperationType: SINGLE_SWING_RIGHT; ParameterTakesPrecedence: no
Type - IfcDoorLiningProperties - LiningDepth: 0.305 m; LiningThickness: 0.04 m
OverallHeight: 2.41 m; OverallWidth: 1.26 m; Material: TI-1F-UZ-ZK
AllplanAttributes (SMT) - Gewerk: Zimmer- und Holzbauarbeiten; V6: 0 m; V7: 0 m; V8: 0 m; V9: 0; Ortscode_Geschoßbezeichnung: E01; Programmversion: 3.1; Objektname: Türmakro; Bezeichnung: SMT; Material: TI-1F-UZ-ZK; Plugin_Bezeichnung: MainObject; Plugin_Objektname: SmartPartCompressed; Glasanteil_berücksichtigen: 100; Version: 7.21; ash T_Sichtschutz: -; ash R_Verweis Wandansicht: -; ash T_Zulage Schachttür: no; ash T_Dichtschließend: no; ash T_Panik: -; ash T_Zarge_Typ: UZ; ash T_Türschließer: OTS; ash T_Gewerk Los: -; ash T_Erforderl. Durchgangsbreite: 0 m; ash T_Türblatt sichtbar 2D: ja; ash T_Zusatzfunktion Panikschloss: -; ash T_Fluchtwegsicherung: -; ash T_Standflügel-Betätigung: -; ash T_Zusatzfunktion Türschließer: -; ash T_Türschließer-Montage: -; ash T_Feststellanlage (FSA): -; ash T_Zusätzliche Rauchmelder: -; ash T_Zusätzl. Anschluss an BMA: -; ash T_Impulsgeber: -; ash T_Sicherheits-Sensorleisten: -; ash T_Anschl. an Zuttrittskontrolle: -; ash T_Anschl. an Einbruchmeld.anl.: -; ash T_Klemmschutz: -; ash T_LV-Positions-Nr.: -; ash T_Plan-Nr.: -; ash T_Sonstiges, Bemerkungen: -; OKFF: 3.75; ash T_Bodentürstopper: -; ash T_nicht abschließbar: no; ash T_Material Seitenteil: -; ash T_Strahlenschutz: 0.000000; ash T_Kantengeometrie: 2F; ash T_Kantenmaterial: PU; ash T_Blatt_Oberfläche: HPL; ash T_Erford. Durgangshöhe: 0 m; ash T_Rammschutz: BL; ash T_Fluchtwegrichtung: -; ash T_Anschlag Gangflügel: -; ash T_Bodendichtung: -; ash T_Lüftungsgitter: 0 m2; ash T_Feuchtebeständigkeit: -; ash T_E_Öffner: -; ash T_Automatik_Antrieb: -; ash T_Sturz: -; ash T_Blatt_Material: HO; ash T_Schlossfunktion: -; ash T_Schliesszylinder: PZ; ash T_Beschlag: DK; ash T_Glasausschnitt: -; ash T_Sonder_Wandmaterial: -; ash T_Anz_Reedkontakte: 0; ash T_Anz_Riegelkontakte: 0; ash T_Schallschutz: -; ash T_Zarge_Material: ST; ash T_Bodeneinstand: -; ash T_Raum zugehörigkeit: BS; ash T_Blatt_Farbe: -; Positionsnummer_Text: U100; Attributset-Objekt: Door; Abrechnungsart: St
AllplanQuantities - GlassSurface: 0; HeightWindowSillOutside: 0; HeightWindowSillInside: 0; OffsetOpeningBottom: 150; OffsetOpeningTop: 0; OffsetOpeningLeft: 0; OffsetOpeningRight: 0; DeductionOpeningBottom: 100; DeductionOpeningLeft: 40; DeductionOpeningRight: 40; DeductionOpeningTop: 40
Pset_DoorCommon - Status: NEW; IsExternal: no; FireRating: EI2 30; ThermalTransmittance: 0 W/K/m2; HandicapAccessible: no; SmokeStop: yes; SelfClosing: yes; FireExit: no
Name | Text1 | ash T_Tür-Nr. | P_ID | Allright_Bauteil_ID
SMT | 19 | E01-001-001-19 | 1166Rau0000033094 | 1163Mak0812442215
SMT | 20 | E01-002-001-20 | 1166Rau0000033107 | 1163Mak0812442211

# IfcDoor: SMT
In: H2 Ebene +1
Type - PredefinedType: DOOR; OperationType: SINGLE_SWING_RIGHT; ParameterTakesPrecedence: no
Type - IfcDoorLiningProperties - LiningDepth: 0.31 m; LiningThickness: 0.04 m
OverallHeight: 2.41 m; OverallWidth: 0.76 m; Material: TI-1F-UZ-D
AllplanAttributes (SMT) - Gewerk: Metallbau-, Schlosserarbeiten; V6: 0 m; V7: 0 m; V8: 0 m; V9: 0; Ortscode_Geschoßbezeichnung: E01; Programmversion: 3.1; Objektname: Türmakro; Text1: 18; Bezeichnung: SMT; Material: TI-1F-UZ-D; Plugin_Bezeichnung: MainObject; Plugin_Objektname: SmartPartCompressed; Glasanteil_berücksichtigen: 100; Version: 7.21; ash T_Sichtschutz: -; ash R_Verweis Wandansicht: -; ash T_Zulage Schachttür: no; ash T_Dichtschließend: no; ash T_Panik: -; ash T_Zarge_Typ: UZ; ash T_Türschließer: OTS; ash T_Gewerk Los: -; ash T_Erforderl. Durchgangsbreite: 0 m; ash T_Türblatt sichtbar 2D: ja; ash T_Zusatzfunktion Panikschloss: -; ash T_Fluchtwegsicherung: -; ash T_Standflügel-Betätigung: -; ash T_Zusatzfunktion Türschließer: -; ash T_Türschließer-Montage: -; ash T_Feststellanlage (FSA): -; ash T_Zusätzliche Rauchmelder: -; ash T_Zusätzl. Anschluss an BMA: -; ash T_Impulsgeber: -; ash T_Sicherheits-Sensorleisten: -; ash T_Anschl. an Einbruchmeld.anl.: -; ash T_Klemmschutz: -; ash T_LV-Positions-Nr.: -; ash T_Plan-Nr.: -; ash T_Sonstiges, Bemerkungen: -; OKFF: 3.75; ash T_Bodentürstopper: -; ash T_nicht abschließbar: no; ash T_Material Seitenteil: -; ash T_Strahlenschutz: 0.000000; ash T_Tür-Nr.: E01-S01-001-18; ash T_Kantengeometrie: 2F; ash T_Kantenmaterial: PU; ash T_Blatt_Oberfläche: HPL; ash T_Erford. Durgangshöhe: 0 m; ash T_Rammschutz: BL; ash T_Fluchtwegrichtung: -; ash T_Anschlag Gangflügel: -; ash T_Bodendichtung: -; ash T_Lüftungsgitter: 0 m2; ash T_Feuchtebeständigkeit: -; ash T_E_Öffner: -; ash T_Automatik_Antrieb: -; ash T_Sturz: -; ash T_Blatt_Material: HO; ash T_Schlossfunktion: -; ash T_Schliesszylinder: PZ; ash T_Beschlag: KD; ash T_Glasausschnitt: -; ash T_Sonder_Wandmaterial: -; ash T_Anz_Reedkontakte: 0; ash T_Anz_Riegelkontakte: 0; ash T_Schallschutz: -; ash T_Zarge_Material: ST; ash T_Bodeneinstand: -; ash T_Raum zugehörigkeit: BS; ash T_Blatt_Farbe: -; Positionsnummer_Text: U100; Attributset-Objekt: Door; P_ID: 1165Rau0000004666; Allright_Bauteil_ID: 1163Mak0812943644; Abrechnungsart: St
AllplanQuantities - GlassSurface: 0; HeightWindowSillOutside: 0; HeightWindowSillInside: 0; OffsetOpeningBottom: 150; OffsetOpeningTop: 0; OffsetOpeningLeft: 0; OffsetOpeningRight: 0; DeductionOpeningBottom: 100; DeductionOpeningLeft: 40; DeductionOpeningRight: 40; DeductionOpeningTop: 40
Pset_DoorCommon - Status: NEW; IsExternal: no; FireRating: EI2 30; ThermalTransmittance: 0 W/K/m2; HandicapAccessible: no; SmokeStop: yes; SelfClosing: yes; FireExit: no

# IfcDoor: SMT (7)
Type - PredefinedType: DOOR; OperationType: SINGLE_SWING_RIGHT; ParameterTakesPrecedence: no
Type - IfcDoorLiningProperties - LiningDepth: 0.32 m; LiningThickness: 0.04 m
AllplanAttributes (SMT) - V6: 0 m; V7: 0 m; V8: 0 m; V9: 0; Programmversion: 3.1; Bezeichnung: SMT; Plugin_Bezeichnung: MainObject; Plugin_Objektname: SmartPartCompressed; Glasanteil_berücksichtigen: 100; Version: 7.21; ash T_Zulage Schachttür: no; ash T_Erforderl. Durchgangsbreite: 0 m; ash T_Türblatt sichtbar 2D: ja; ash T_Feststellanlage (FSA): -; ash T_nicht abschließbar: no; ash T_Erford. Durgangshöhe: 0 m; ash T_Lüftungsgitter: 0 m2; ash T_Anz_Reedkontakte: 0; ash T_Anz_Riegelkontakte: 0; ash T_Schallschutz: -; Attributset-Objekt: Door; Abrechnungsart: St
AllplanQuantities - GlassSurface: 0; HeightWindowSillOutside: 0; HeightWindowSillInside: 0; OffsetOpeningTop: 0; OffsetOpeningLeft: 0; OffsetOpeningRight: 0; DeductionOpeningBottom: 100; DeductionOpeningLeft: 40; DeductionOpeningRight: 40; DeductionOpeningTop: 40
Pset_DoorCommon - Status: NEW; IsExternal: no; ThermalTransmittance: 0 W/K/m2; HandicapAccessible: no; FireExit: no
Name | In | OverallHeight (m) | OverallWidth (m) | Material = AllplanAttributes (SMT), Material | Gewerk | Ortscode_Geschoßbezeichnung | Text1 | ash T_Dichtschließend | ash T_Zarge_Typ | ash T_Türschließer | OKFF | ash T_Strahlenschutz | ash T_Tür-Nr. | ash T_Kantengeometrie | ash T_Blatt_Oberfläche | ash T_Anschlag Gangflügel | ash T_Blatt_Material | ash T_Schliesszylinder | ash T_Beschlag | ash T_Zarge_Material | ash T_Raum zugehörigkeit | P_ID | Allright_Bauteil_ID | Objektname | OffsetOpeningBottom | FireRating | SmokeStop = SelfClosing | ash T_Kantenmaterial | ash T_Feuchtebeständigkeit | ash T_Panik = ash T_Zusatzfunktion Panikschloss = ash T_Fluchtwegsicherung = ash T_Standflügel-Betätigung = ash T_Zusatzfunktion Türschließer = ash T_Türschließer-Montage = ash T_Zusätzliche Rauchmelder = ash T_Zusätzl. Anschluss an BMA = ash T_Impulsgeber = ash T_Sicherheits-Sensorleisten = ash T_Anschl. an Einbruchmeld.anl. = ash T_Klemmschutz = ash T_Bodentürstopper = ash T_Fluchtwegrichtung = ash T_Bodendichtung = ash T_Automatik_Antrieb = ash T_Bodeneinstand | ash T_Rammschutz | ash T_Sturz | ash T_Sichtschutz = ash R_Verweis Wandansicht = ash T_Gewerk Los = ash T_LV-Positions-Nr. = ash T_Plan-Nr. = ash T_Sonstiges, Bemerkungen = ash T_Material Seitenteil = ash T_E_Öffner = ash T_Schlossfunktion = ash T_Glasausschnitt = ash T_Sonder_Wandmaterial = ash T_Blatt_Farbe
SMT | H2 Ebene +3 | 2.41 | 1.26 | TI-1F-UZ-D | Betonarbeiten | E03 | 15 | no | UZ | OTS | 11.25 | 0.000000 | E03-F02-001-15 | LF | L | - | ST | PZ | KD | ST | BS | 1265Rau0000000023 | 1263Mak0812602520 | Türmakro, -SmartPart | 150 | EI2 30 | yes | AllplanAttributes (SMT) - Codetext: Codetext; Text2: -; Funktion: Flurtür; Tragendes Bauteil: yes; Typ: 0; Brennbares Material: no; Brandverhalten: 0; Brandabschnittsdefinierendes Bauteil: no; Brandschutzklasse: A; Pset_DoorCommon - AcousticRating: 0; Reference: Codetext
SMT | H2 Ebene +3 | 2.41 | 1.01 | TI-1F-UZ-D | Metallbau-, Schlosserarbeiten | E03 | 19 | no | UZ | OTS | 11.25 | 0.000000 | E03-010-001-19 | 2F | HPL | - | HO | WC | DD | ST | BGS | 1266Rau0000015290 | 1263Mak0812840395 | Türmakro | 150 | EI2 60 | yes | PU | N | AllplanAttributes (SMT) - Text2: -
SMT | H2 Ebene +3 | 2.41 | 1.01 | TI-1F-UZ-D-N | Metallbau-, Schlosserarbeiten | E03 | 20 | no | UZ | - | 11.25 | 0.000000 | E03-010c-001-20 | LF | L | - | ST | WC | DD | ST | BGS | 1266Rau0812598643 | 1263Mak0812839961 | Türmakro | 150 |  | no | - | N | - | - | - | AllplanAttributes (SMT) - Text2: -; ash T_Laserschutz: -; Pset_DoorCommon - SecurityRating: SA
SMT | H2 Ebene +2 | 2.41 | 0.885 | TI-1F-UZ-D | Metallbau-, Schlosserarbeiten | E02 | 82 | yes | UZ | - | 7.5 |  | E02-052-001-82 | 2F | HPL |  | HO | PZ | DD | ST | BS | 1215Rau0000006905 | 1213Mak0813004766 | Türmakro | 150 | - | no | PU | - | - | BL | - | -
SMT | H2 Ebene +1 | 2.41 | 0.885 | TI-1F-UZ-D | Metallbau-, Schlosserarbeiten | E01 | 82 | yes | UZ | - | 3.75 | 0.000000 | E01-052-001-82 | 2F | HPL | - | HO | PZ | DD | ST | BS | 1165Rau0000004701 | 1163Mak0812551813 | Türmakro | 150 | - | no | PU | - | - | BL | - | - | AllplanAttributes (SMT) - Positionsnummer_Text: U100
SMT | H2 Ebene +1 | 2.41 | 1.01 | TI-1F-UZ-D-N | Zimmer- und Holzbauarbeiten | E01 | 161 | yes | BZ | - | 3.75 | 0.000000 | E01-062-001-161 | 2F | HPL | - | HO | WC | DD | - | BGS | 1165Rau0000004819 | 1163Mak0814777929 | Türmakro | 150 | - | no | PU | - | - | BL | S | - | AllplanAttributes (SMT) - Positionsnummer_Text: U100; ash T_Anschl. an Zuttrittskontrolle: -
SMT | H2 Ebene 0 | 2.46 | 0.885 | TI-1F-UZ-D | Metallbau-, Schlosserarbeiten | E00 | 82 | yes | UZ | - | 0 | 0.000000 | E00-052-001-82 | 2F | HPL | - | HO | PZ | DD | ST | BGS | 1115Rau0000005053 | 1113Mak0812551813 | Türmakro | 200 | - | no | PU | - | - | BL | - | - | AllplanAttributes (SMT) - Positionsnummer_Text: S68

# IfcDoor: SMT
In: H2 Ebene +3
Type - PredefinedType: DOOR; OperationType: SINGLE_SWING_RIGHT; ParameterTakesPrecedence: no
Type - IfcDoorLiningProperties - LiningDepth: 0.321 m; LiningThickness: 0.04 m
OverallHeight: 2.41 m; OverallWidth: 1.01 m; Material: TI-1F-UZ-D
AllplanAttributes (SMT) - Gewerk: Metallbau-, Schlosserarbeiten; V6: 0 m; V7: 0 m; V8: 0 m; V9: 0; Ortscode_Geschoßbezeichnung: E03; Programmversion: 3.0; Objektname: Türmakro; Text1: 33; Text2: -; Bezeichnung: SMT; Material: TI-1F-UZ-D; Plugin_Bezeichnung: MainObject; Plugin_Objektname: SmartPartCompressed; Glasanteil_berücksichtigen: 100; Version: 8.11; ash T_Zulage Schachttür: no; ash T_Dichtschließend: no; ash T_Zarge_Typ: UZ; ash T_Türschließer: OTS; ash T_Erforderl. Durchgangsbreite: 0 m; ash T_Türblatt sichtbar 2D: ja; OKFF: 11.25; ash T_nicht abschließbar: no; ash T_Strahlenschutz: 0.000000; ash T_Tür-Nr.: E03-014-001-33; ash T_Kantengeometrie: LF; ash T_Blatt_Oberfläche: L; ash T_Erford. Durgangshöhe: 0 m; ash T_Anschlag Gangflügel: -; ash T_Lüftungsgitter: 0 m2; ash T_Blatt_Material: ST; ash T_Schliesszylinder: PZ; ash T_Beschlag: KD; ash T_Anz_Reedkontakte: 0; ash T_Anz_Riegelkontakte: 0; ash T_Schallschutz: -; ash T_Zarge_Material: ST; ash T_Raum zugehörigkeit: BGS; Attributset-Objekt: Door; P_ID: 1265Rau0000000023; Allright_Bauteil_ID: 1263Mak0812609564; Abrechnungsart: St
AllplanQuantities - GlassSurface: 0; HeightWindowSillOutside: 0; HeightWindowSillInside: 0; OffsetOpeningBottom: 150; OffsetOpeningTop: 0; OffsetOpeningLeft: 0; OffsetOpeningRight: 0; DeductionOpeningBottom: 100; DeductionOpeningLeft: 40; DeductionOpeningRight: 40; DeductionOpeningTop: 40
Pset_DoorCommon - Status: NEW; IsExternal: no; FireRating: EI2 30; ThermalTransmittance: 0 W/K/m2; HandicapAccessible: no; SmokeStop: yes; SelfClosing: yes; FireExit: no

# IfcDoor: SMT
In: H2 Ebene +1
Type - PredefinedType: DOOR; OperationType: SINGLE_SWING_RIGHT; ParameterTakesPrecedence: no
Type - IfcDoorLiningProperties - LiningDepth: 0.328 m; LiningThickness: 0.04 m
OverallHeight: 2.41 m; OverallWidth: 1.01 m; Material: TI-1F-UZ-D
AllplanAttributes (SMT) - Gewerk: Zimmer- und Holzbauarbeiten; V6: 0 m; V7: 0 m; V8: 0 m; V9: 0; Ortscode_Geschoßbezeichnung: E01; Programmversion: 3.1; Objektname: Türmakro; Text1: 21; Bezeichnung: SMT; Material: TI-1F-UZ-D; Plugin_Bezeichnung: MainObject; Plugin_Objektname: SmartPartCompressed; Glasanteil_berücksichtigen: 100; Version: 7.21; ash T_Sichtschutz: -; ash R_Verweis Wandansicht: -; ash T_Zulage Schachttür: no; ash T_Dichtschließend: no; ash T_Panik: -; ash T_Zarge_Typ: UZ; ash T_Türschließer: -; ash T_Gewerk Los: -; ash T_Erforderl. Durchgangsbreite: 0 m; ash T_Türblatt sichtbar 2D: ja; ash T_Zusatzfunktion Panikschloss: -; ash T_Fluchtwegsicherung: -; ash T_Standflügel-Betätigung: -; ash T_Zusatzfunktion Türschließer: -; ash T_Türschließer-Montage: -; ash T_Feststellanlage (FSA): -; ash T_Zusätzliche Rauchmelder: -; ash T_Zusätzl. Anschluss an BMA: -; ash T_Impulsgeber: -; ash T_Sicherheits-Sensorleisten: -; ash T_Anschl. an Zuttrittskontrolle: -; ash T_Anschl. an Einbruchmeld.anl.: -; ash T_Klemmschutz: -; ash T_LV-Positions-Nr.: -; ash T_Plan-Nr.: -; ash T_Sonstiges, Bemerkungen: -; OKFF: 3.75; ash T_Bodentürstopper: -; ash T_nicht abschließbar: no; ash T_Material Seitenteil: -; ash T_Strahlenschutz: 0.000000; ash T_Tür-Nr.: E01-003-001-21; ash T_Kantengeometrie: 2F; ash T_Kantenmaterial: PU; ash T_Blatt_Oberfläche: HPL; ash T_Erford. Durgangshöhe: 0 m; ash T_Rammschutz: BL; ash T_Fluchtwegrichtung: -; ash T_Anschlag Gangflügel: -; ash T_Bodendichtung: Ja; ash T_Lüftungsgitter: 0 m2; ash T_Feuchtebeständigkeit: -; ash T_E_Öffner: -; ash T_Automatik_Antrieb: -; ash T_Sturz: -; ash T_Blatt_Material: HO; ash T_Schlossfunktion: -; ash T_Schliesszylinder: PZ; ash T_Beschlag: KD; ash T_Glasausschnitt: -; ash T_Sonder_Wandmaterial: -; ash T_Anz_Reedkontakte: 0; ash T_Anz_Riegelkontakte: 0; ash T_Schallschutz: 27 dB; ash T_Zarge_Material: ST; ash T_Bodeneinstand: -; ash T_Raum zugehörigkeit: BGS; ash T_Blatt_Farbe: -; Positionsnummer_Text: U100; Attributset-Objekt: Door; P_ID: 1165Rau0000004808; Allright_Bauteil_ID: 1163Mak0812447346; Abrechnungsart: St
AllplanQuantities - GlassSurface: 0; HeightWindowSillOutside: 0; HeightWindowSillInside: 0; OffsetOpeningBottom: 150; OffsetOpeningTop: 0; OffsetOpeningLeft: 0; OffsetOpeningRight: 0; DeductionOpeningBottom: 100; DeductionOpeningLeft: 40; DeductionOpeningRight: 40; DeductionOpeningTop: 40
Pset_DoorCommon - Status: NEW; IsExternal: no; ThermalTransmittance: 0 W/K/m2; HandicapAccessible: no; SmokeStop: no; SelfClosing: no; FireExit: no

# IfcDoor: SMT
In: H2 Ebene +2
Type - PredefinedType: DOOR; OperationType: SINGLE_SWING_RIGHT; ParameterTakesPrecedence: no
Type - IfcDoorLiningProperties - LiningDepth: 0.329 m; LiningThickness: 0.04 m
OverallHeight: 2.41 m; OverallWidth: 1.26 m; Material: TI-1F-UZ-D
AllplanAttributes (SMT) - Gewerk: Zimmer- und Holzbauarbeiten; V6: 0 m; V7: 0 m; V8: 0 m; V9: 0; Ortscode_Geschoßbezeichnung: E02; Programmversion: 3.1; Objektname: Türmakro; Text1: 17; Bezeichnung: SMT; Material: TI-1F-UZ-D; Plugin_Bezeichnung: MainObject; Plugin_Objektname: SmartPartCompressed; Glasanteil_berücksichtigen: 100; Version: 7.21; ash T_Sichtschutz: -; ash R_Verweis Wandansicht: -; ash T_Zulage Schachttür: no; ash T_Dichtschließend: no; ash T_Panik: -; ash T_Zarge_Typ: UZ; ash T_Türschließer: OTS; ash T_Gewerk Los: -; ash T_Erforderl. Durchgangsbreite: 0 m; ash T_Türblatt sichtbar 2D: ja; ash T_Zusatzfunktion Panikschloss: -; ash T_Fluchtwegsicherung: -; ash T_Standflügel-Betätigung: -; ash T_Zusatzfunktion Türschließer: -; ash T_Türschließer-Montage: -; ash T_Feststellanlage (FSA): EMF; ash T_Zusätzliche Rauchmelder: -; ash T_Zusätzl. Anschluss an BMA: -; ash T_Impulsgeber: -; ash T_Sicherheits-Sensorleisten: -; ash T_Anschl. an Zuttrittskontrolle: -; ash T_Anschl. an Einbruchmeld.anl.: -; ash T_Klemmschutz: -; ash T_LV-Positions-Nr.: -; ash T_Plan-Nr.: -; ash T_Sonstiges, Bemerkungen: -; OKFF: 7.5; ash T_Bodentürstopper: -; ash T_nicht abschließbar: no; ash T_Material Seitenteil: -; ash T_Strahlenschutz: 0.000000; ash T_Tür-Nr.: E02-F02-001-17; ash T_Kantengeometrie: 2F; ash T_Kantenmaterial: PU; ash T_Blatt_Oberfläche: HPL; ash T_Erford. Durgangshöhe: 0 m; ash T_Laserschutz: -; ash T_Rammschutz: BL; ash T_Fluchtwegrichtung: -; ash T_Anschlag Gangflügel: -; ash T_Bodendichtung: -; ash T_Lüftungsgitter: 0 m2; ash T_Feuchtebeständigkeit: -; ash T_Automatik_Antrieb: -; ash T_Sturz: -; ash T_Blatt_Material: HO; ash T_Schlossfunktion: E; ash T_Schliesszylinder: PZ; ash T_Beschlag: DK; ash T_Glasausschnitt: 35x100; ash T_Sonder_Wandmaterial: -; ash T_Anz_Reedkontakte: 0; ash T_Anz_Riegelkontakte: 1; ash T_Schallschutz: -; ash T_Zarge_Material: ST; ash T_Bodeneinstand: -; ash T_Raum zugehörigkeit: BS; ash T_Blatt_Farbe: -; ash T_Steuerung (BG): E; ash T_Steuerung (BS): B, E; Attributset-Objekt: Door; P_ID: 1215Rau0000006938; Allright_Bauteil_ID: 1213Mak0813751187; Abrechnungsart: St
AllplanQuantities - GlassSurface: 0; HeightWindowSillOutside: 0; HeightWindowSillInside: 0; OffsetOpeningBottom: 150; OffsetOpeningTop: 0; OffsetOpeningLeft: 0; OffsetOpeningRight: 0; DeductionOpeningBottom: 100; DeductionOpeningLeft: 40; DeductionOpeningRight: 40; DeductionOpeningTop: 40
Pset_DoorCommon - Status: NEW; IsExternal: no; FireRating: EI2 30; ThermalTransmittance: 0 W/K/m2; HandicapAccessible: no; SmokeStop: yes; SelfClosing: yes; FireExit: no

# IfcDoor: SMT (22)
Type - PredefinedType: DOOR; OperationType: SINGLE_SWING_RIGHT; ParameterTakesPrecedence: no
Type - IfcDoorLiningProperties - LiningDepth: 0.337 m; LiningThickness: 0.04 m
AllplanAttributes (SMT) - V6: 0 m; V7: 0 m; V8: 0 m; V9: 0; Programmversion: 3.1; Objektname: Türmakro; Bezeichnung: SMT; Plugin_Bezeichnung: MainObject; Plugin_Objektname: SmartPartCompressed; Glasanteil_berücksichtigen: 100; Version: 7.21; ash T_Sichtschutz: -; ash R_Verweis Wandansicht: -; ash T_Zulage Schachttür: no; ash T_Panik: -; ash T_Gewerk Los: -; ash T_Erforderl. Durchgangsbreite: 0 m; ash T_Türblatt sichtbar 2D: ja; ash T_Zusatzfunktion Panikschloss: -; ash T_Fluchtwegsicherung: -; ash T_Standflügel-Betätigung: -; ash T_Zusatzfunktion Türschließer: -; ash T_Türschließer-Montage: -; ash T_Zusätzliche Rauchmelder: -; ash T_Zusätzl. Anschluss an BMA: -; ash T_Impulsgeber: -; ash T_Sicherheits-Sensorleisten: -; ash T_Anschl. an Einbruchmeld.anl.: -; ash T_Klemmschutz: -; ash T_LV-Positions-Nr.: -; ash T_Plan-Nr.: -; ash T_Sonstiges, Bemerkungen: -; ash T_Bodentürstopper: -; ash T_nicht abschließbar: no; ash T_Material Seitenteil: -; ash T_Kantengeometrie: 2F; ash T_Kantenmaterial: PU; ash T_Blatt_Oberfläche: HPL; ash T_Erford. Durgangshöhe: 0 m; ash T_Rammschutz: BL; ash T_Fluchtwegrichtung: -; ash T_Bodendichtung: -; ash T_Lüftungsgitter: 0 m2; ash T_E_Öffner: -; ash T_Automatik_Antrieb: -; ash T_Blatt_Material: HO; ash T_Schlossfunktion: -; ash T_Sonder_Wandmaterial: -; ash T_Anz_Riegelkontakte: 0; ash T_Schallschutz: -; ash T_Bodeneinstand: -; ash T_Blatt_Farbe: -; Attributset-Objekt: Door; Abrechnungsart: St
AllplanQuantities - GlassSurface: 0; HeightWindowSillOutside: 0; HeightWindowSillInside: 0; OffsetOpeningTop: 0; OffsetOpeningLeft: 0; OffsetOpeningRight: 0; DeductionOpeningBottom: 100; DeductionOpeningLeft: 40; DeductionOpeningRight: 40; DeductionOpeningTop: 40
Pset_DoorCommon - Status: NEW; IsExternal: no; ThermalTransmittance: 0 W/K/m2; HandicapAccessible: no; FireExit: no
Name | In | OverallHeight (m) | OverallWidth (m) | Material = AllplanAttributes (SMT), Material | Gewerk | Ortscode_Geschoßbezeichnung | Text1 | ash T_Dichtschließend | ash T_Zarge_Typ | ash T_Türschließer | ash T_Feststellanlage (FSA) | OKFF | ash T_Strahlenschutz | ash T_Tür-Nr. | ash T_Anschlag Gangflügel | ash T_Feuchtebeständigkeit | ash T_Sturz | ash T_Schliesszylinder | ash T_Beschlag | ash T_Glasausschnitt | ash T_Anz_Reedkontakte | ash T_Zarge_Material | ash T_Raum zugehörigkeit | P_ID | Allright_Bauteil_ID | OffsetOpeningBottom | SmokeStop = SelfClosing | Positionsnummer_Text
SMT | H2 Ebene +2 | 2.41 | 1.259 | TI-1F-UZ-D | Metallbau-, Schlosserarbeiten | E02 | 91 | no | UZ | OTS | FL | 7.5 | 0.000000 | E02-050-001-91 | - | - | - | PZ | DD | - | 1 | ST | BGS | 1215Rau0000006905 | 1213Mak0813057877 | 150 | yes | AllplanAttributes (SMT) - ash T_Anschl. an Zuttrittskontrolle: -; ash T_Laserschutz: -; ash T_Material Oberlicht: -; ash T_Steuerung (BS): I; Pset_DoorCommon - SecurityRating: SA
SMT | H2 Ebene +2 | 2.41 | 1.01 | TI-1F-UZ-D | Zimmer- und Holzbauarbeiten | E02 | 93 | yes | UZ | - | - | 7.5 |  | E02-051-001-93 | - | N | - | PZ | DD | - | 0 | ST | BS | 1216Rau0000047157 | 1213Mak0813056722 | 150 | no | Pset_DoorCommon - FireRating: -
SMT | H2 Ebene +2 | 2.41 | 1.259 | TI-1F-UZ-D | Metallbau-, Schlosserarbeiten | E02 | 86 | no | UZ | OTS | FL | 7.5 | 0.000000 | E02-F08-001-86 | - | - | - | PZ | DD |  | 1 | ST | BS | 1215Rau0000006905 | 1213Mak0813004206 | 150 | yes | AllplanAttributes (SMT) - ash T_Anschl. an Zuttrittskontrolle: -; ash T_Laserschutz: -; ash T_Material Oberlicht: -; ash T_Steuerung (BS): I; Pset_DoorCommon - SecurityRating: SA
SMT | H2 Ebene +2 | 2.41 | 1.01 | TI-1F-UZ-D | Metallbau-, Schlosserarbeiten | E02 | 130 | no | UZ | OTS | - | 7.5 |  | E02-081-001-130 |  | - | - | PZ | KD | - | 0 | ST | BGS | 1215Rau0000006932 | 1213Mak0813004145 | 150 | yes | Pset_DoorCommon - FireRating: EI2 30
SMT | H2 Ebene +2 | 2.41 | 1.135 | TI-1F-UZ-D | Zimmer- und Holzbauarbeiten | E02 | 53 | yes | UZ | - | - | 7.5 |  | E02-039-001-53 |  | N | - | Kn-PZ | KD | - | 0 | ST | BGS | 1215Rau0000006899 | 1213Mak0813004733 | 150 | no | Pset_DoorCommon - FireRating: -
SMT | H2 Ebene +2 | 2.41 | 1.01 | TI-1F-UZ-D | Zimmer- und Holzbauarbeiten | E02 | 52 | no | UZ | OTS | - | 7.5 |  | E02-038-001-52 |  | - | - | PZ | KD | - | 0 | ST | BGS | 1215Rau0000006899 | 1213Mak0813641458 | 150 | yes
SMT | H2 Ebene +2 | 2.41 | 1.01 | TI-1F-UZ-D | Zimmer- und Holzbauarbeiten | E02 | 122 | no | UZ | OTS | - | 7.5 |  | E02-077-001-122 |  | - | - | PZ | KD | - | 0 | ST | BGS | 1215Rau0000006914 | 1213Mak0813004377 | 150 | yes
SMT | H2 Ebene +2 | 2.41 | 1.135 | TI-1F-UZ-D | Zimmer- und Holzbauarbeiten | E02 | 121 | yes | UZ | - | - | 7.5 |  | E02-076-001-121 | - | N | - | Kn-PZ | KD | - | 0 | ST | BGS | 1215Rau0000006914 | 1213Mak0813688321 | 150 | no | Pset_DoorCommon - FireRating: -
SMT | H2 Ebene +2 | 2.41 | 1.01 | TI-1F-UZ-D | Metallbau-, Schlosserarbeiten | E02 | 44 | no | UZ | OTS | - | 7.5 |  | E02-029-001-44 |  | - | - | PZ | KD | - | 0 | ST | BGS | 1215Rau0000006929 | 1213Mak0813004139 | 150 | yes | Pset_DoorCommon - FireRating: EI2 30
SMT | H2 Ebene +1 | 2.41 | 1.01 | TI-1F-UZ-ZK | Zimmer- und Holzbauarbeiten | E01 | 122 | no | BZ | OTS | - | 3.75 | 0.000000 | E01-077-001-122 | - | - | S | PZ | KD | - | 0 | - | BGS | 1165Rau0000004712 | 1163Mak0812436193 | 150 | yes | U100
SMT | H2 Ebene +1 | 2.41 | 1.26 | TI-1F-UZ-M-ZK-SF | Metallbau-, Schlosserarbeiten | E01 | 86 | no | UZ | OTS | FL | 3.75 | 0.000000 | E01-048-001-86 | - | - | - | PZ | DD |  | 1 | ST | BS | 1165Rau0000004701 | 1163Mak0812551921 | 150 | yes | U100 | AllplanAttributes (SMT) - ash T_Anschl. an Zuttrittskontrolle: -; ash T_Laserschutz: -; ash T_Material Oberlicht: -; ash T_Steuerung (BS): I; Pset_DoorCommon - SecurityRating: SA
SMT | H2 Ebene +1 | 2.41 | 1.135 | TI-1F-UZ-D-N | Zimmer- und Holzbauarbeiten | E01 | 53 | yes | UZ | - | - | 3.75 | 0.000000 | E01-039-001-53 | - | N | - | Kn-PZ | KD | - | 0 | ST | BGS | 1165Rau0000004688 | 1163Mak0812442293 | 150 | no | U100 | Pset_DoorCommon - FireRating: -
SMT | H2 Ebene +1 | 2.41 | 1.01 | TI-1F-UZ-ZK | Zimmer- und Holzbauarbeiten | E01 | 52 | no | UZ | OTS | - | 3.75 | 0.000000 | E01-038-001-52 | - | - | - | PZ | KD | - | 0 | ST | BGS | 1165Rau0000004688 | 1163Mak0814537108 | 150 | yes | U100
SMT | H2 Ebene +1 | 2.41 | 1.26 | TI-1F-UZ-M-ZK-SF | Metallbau-, Schlosserarbeiten | E01 | 91 | no | UZ | OTS | FL | 3.75 | 0.000000 | E01-050-001-91 | - | - | - | PZ | DD | - | 1 | ST | BS | 1165Rau0000004701 | 1163Mak0812551489 | 150 | yes | U100 | AllplanAttributes (SMT) - ash T_Anschl. an Zuttrittskontrolle: -; ash T_Laserschutz: -; ash T_Material Oberlicht: -; ash T_Steuerung (BS): I; Pset_DoorCommon - SecurityRating: SA
SMT | H2 Ebene +1 | 2.41 | 1.01 | TI-1F-UZ-D-N | Metallbau-, Schlosserarbeiten | E01 | 93 | yes | UZ | - | - | 3.75 | 0.000000 | E01-051-001-93 | - | N | - | PZ | DD | - | 0 | ST | BS | 1166Rau0000033829 | 1163Mak0812551491 | 150 | no | U100 | Pset_DoorCommon - FireRating: -
SMT | H2 Ebene 0 | 2.46 | 1.01 | TI-1F-UZ-ZK | Zimmer- und Holzbauarbeiten | E00 | 122 | no | UZ | OTS | - | 0 | 0.000000 | E00-077-001-122 | - | - | - | PZ | KD | - | 0 | ST | BGS | 1115Rau0000005223 | 1113Mak0812436193 | 200 | yes | S68
SMT | H2 Ebene 0 | 2.46 | 1.135 | TI-1F-UZ-D-N | Zimmer- und Holzbauarbeiten | E00 | 121 | yes | UZ | - | - | 0 | 0.000000 | E00-076-001-121 | - | N | - | Kn-PZ | KD | - | 0 | ST | BGS | 1115Rau0000005223 | 1113Mak0812436083 | 200 | no | S68 | Pset_DoorCommon - FireRating: -
SMT | H2 Ebene 0 | 2.46 | 1.135 | TI-1F-UZ-ZK | Zimmer- und Holzbauarbeiten | E00 | 53 | yes | UZ | - | - | 0 | 0.000000 | E00-039-001-53 | - | N | - | Kn-PZ | KD | - | 0 | ST | BGS | 1115Rau0000005169 | 1113Mak0812442293 | 200 | no | S68 | Pset_DoorCommon - FireRating: -
SMT | H2 Ebene 0 | 2.46 | 1.01 | TI-1F-UZ-ZK | Zimmer- und Holzbauarbeiten | E00 | 52 | no | UZ | OTS | - | 0 | 0.000000 | E00-038-001-52 | - | - | - | PZ | KD | - | 0 | ST | BGS | 1115Rau0000005169 | 1113Mak0814179251 | 200 | yes | S68
SMT | H2 Ebene 0 | 2.46 | 1.26 | TI-1F-UZ-M-ZK-SF | Metallbau-, Schlosserarbeiten | E00 | 86 | no | UZ | OTS | FL | 0 | 0.000000 | E00-048-001-86 | - | - | - | PZ | DD |  | 1 | ST | BGS | 1115Rau0000005053 | 1113Mak0814233853 | 200 | yes | S68 | AllplanAttributes (SMT) - ash T_Anschl. an Zuttrittskontrolle: -; ash T_Laserschutz: -; ash T_Material Oberlicht: -; ash T_Steuerung (BS): I; Pset_DoorCommon - SecurityRating: SA
SMT | H2 Ebene 0 | 2.46 | 1.259 | TI-1F-UZ-M-ZK-SF | Metallbau-, Schlosserarbeiten | E00 | 91 | no | UZ | OTS | FL | 0 | 0.000000 | E00-050-001-91 | - | - | - | PZ | DD | - | 1 | ST | BGS | 1116Rau0000065837 | 1113Mak0812551489 | 200 | yes | S68 | AllplanAttributes (SMT) - ash T_Anschl. an Zuttrittskontrolle: -; ash T_Laserschutz: -; ash T_Material Oberlicht: -; ash T_Steuerung (BS): I; Pset_DoorCommon - SecurityRating: SA
SMT | H2 Ebene 0 | 2.46 | 1.01 | TI-1F-UZ-D-N | Metallbau-, Schlosserarbeiten | E00 | 93 | yes | UZ | - | - | 0 | 0.000000 | E00-051-001-93 | - | N | - | PZ | DD | - | 0 | ST | BS | 1116Rau0000065690 | 1113Mak0812551491 | 200 | no | S68 | Pset_DoorCommon - FireRating: -

# IfcDoor: SMT (17)
Type - PredefinedType: DOOR; OperationType: SINGLE_SWING_RIGHT; ParameterTakesPrecedence: no
Type - IfcDoorLiningProperties - LiningDepth: 0.351 m; LiningThickness: 0.04 m
AllplanAttributes (SMT) - Gewerk: Zimmer- und Holzbauarbeiten; V6: 0 m; V7: 0 m; V8: 0 m; V9: 0; Programmversion: 3.1; Objektname: Türmakro; Bezeichnung: SMT; Plugin_Bezeichnung: MainObject; Plugin_Objektname: SmartPartCompressed; Glasanteil_berücksichtigen: 100; Version: 7.21; ash T_Sichtschutz: -; ash R_Verweis Wandansicht: -; ash T_Zulage Schachttür: no; ash T_Panik: -; ash T_Zarge_Typ: UZ; ash T_Gewerk Los: -; ash T_Erforderl. Durchgangsbreite: 0 m; ash T_Türblatt sichtbar 2D: ja; ash T_Zusatzfunktion Panikschloss: -; ash T_Fluchtwegsicherung: -; ash T_Standflügel-Betätigung: -; ash T_Zusatzfunktion Türschließer: -; ash T_Türschließer-Montage: -; ash T_Feststellanlage (FSA): -; ash T_Zusätzliche Rauchmelder: -; ash T_Zusätzl. Anschluss an BMA: -; ash T_Impulsgeber: -; ash T_Sicherheits-Sensorleisten: -; ash T_Anschl. an Einbruchmeld.anl.: -; ash T_Klemmschutz: -; ash T_LV-Positions-Nr.: -; ash T_Plan-Nr.: -; ash T_Sonstiges, Bemerkungen: -; ash T_Bodentürstopper: -; ash T_nicht abschließbar: no; ash T_Material Seitenteil: -; ash T_Kantengeometrie: 2F; ash T_Kantenmaterial: PU; ash T_Blatt_Oberfläche: HPL; ash T_Erford. Durgangshöhe: 0 m; ash T_Rammschutz: BL; ash T_Fluchtwegrichtung: -; ash T_Lüftungsgitter: 0 m2; ash T_Feuchtebeständigkeit: -; ash T_E_Öffner: -; ash T_Automatik_Antrieb: -; ash T_Sturz: -; ash T_Blatt_Material: HO; ash T_Schlossfunktion: -; ash T_Schliesszylinder: PZ; ash T_Glasausschnitt: -; ash T_Sonder_Wandmaterial: -; ash T_Anz_Reedkontakte: 0; ash T_Anz_Riegelkontakte: 0; ash T_Zarge_Material: ST; ash T_Bodeneinstand: -; ash T_Blatt_Farbe: -; Attributset-Objekt: Door; Abrechnungsart: St
AllplanQuantities - GlassSurface: 0; HeightWindowSillOutside: 0; HeightWindowSillInside: 0; OffsetOpeningTop: 0; OffsetOpeningLeft: 0; OffsetOpeningRight: 0; DeductionOpeningBottom: 100; DeductionOpeningLeft: 40; DeductionOpeningRight: 40; DeductionOpeningTop: 40
Pset_DoorCommon - Status: NEW; IsExternal: no; ThermalTransmittance: 0 W/K/m2; HandicapAccessible: no; FireExit: no
Name | In | OverallHeight (m) | OverallWidth (m) | Material = AllplanAttributes (SMT), Material | Ortscode_Geschoßbezeichnung | Text1 | ash T_Dichtschließend | ash T_Türschließer | OKFF | ash T_Tür-Nr. | ash T_Bodendichtung | ash T_Beschlag | ash T_Schallschutz | ash T_Raum zugehörigkeit | P_ID | Allright_Bauteil_ID | OffsetOpeningBottom | SmokeStop = SelfClosing
SMT | H2 Ebene +2 | 2.41 | 1.135 | TI-1F-UZ-D | E02 | 77 | no | OTS | 7.5 | E02-011-001-77 | - | DK | - | BS | 1216Rau0000046587 | 1213Mak0813004739 | 150 | yes | Pset_DoorCommon - FireRating: EI2 30
SMT | H2 Ebene +2 | 2.41 | 1.01 | TI-1F-UZ-D | E02 | 124 | yes | - | 7.5 | E02-086-001-124 | Ja | DK | 27 dB | BS | 1216Rau0000047443 | 1213Mak0813240140 | 150 | no
SMT | H2 Ebene +2 | 2.41 | 1.01 | TI-1F-UZ-D | E02 | 126 | yes | - | 7.5 | E02-085-001-126 | Ja | DK | 27 dB | BS | 1216Rau0000047457 | 1213Mak0813245398 | 150 | no
SMT | H2 Ebene +2 | 2.41 | 1.01 | TI-1F-UZ-D | E02 | 129 | yes | - | 7.5 | E02-084-001-129 | Ja | DK | 27 dB | BS | 1216Rau0000047633 | 1213Mak0813239232 | 150 | no
SMT | H2 Ebene +2 | 2.41 | 1.01 | TI-1F-UZ-D | E02 | 131 | yes | - | 7.5 | E02-083-001-131 | Ja | DK | 27 dB | BS | 1216Rau0000047471 | 1213Mak0813004353 | 150 | no
SMT | H2 Ebene +2 | 2.41 | 1.135 | TI-1F-UZ-D | E02 | 98 | no | OTS | 7.5 | E02-065-001-98 | - | DK | - | BS | 1216Rau0000047195 | 1213Mak0813004472 | 150 | yes | Pset_DoorCommon - FireRating: EI2 30
SMT | H2 Ebene +2 | 2.41 | 1.01 | TI-1F-UZ-D | E02 | 50 | yes | - | 7.5 | E02-033-001-50 | Ja | DK | 27 dB | BS | 1216Rau0000046083 | 1213Mak0813643223 | 150 | no
SMT | H2 Ebene +2 | 2.41 | 1.01 | TI-1F-UZ-D | E02 | 48 | yes | - | 7.5 | E02-034-001-48 | Ja | DK | 27 dB | BS | 1216Rau0000046097 | 1213Mak0813643211 | 150 | no
SMT | H2 Ebene +2 | 2.41 | 1.01 | TI-1F-UZ-D | E02 | 42 | yes | - | 7.5 | E02-036-001-42 | Ja | DK | 27 dB | BS | 1216Rau0000046111 | 1213Mak0813642522 | 150 | no
SMT | H2 Ebene +2 | 2.41 | 1.01 | TI-1F-UZ-D | E02 | 45 | yes | - | 7.5 | E02-035-001-45 | Ja | DK | 27 dB | BS | 1216Rau0000047619 | 1213Mak0813643697 | 150 | no
SMT | H2 Ebene 0 | 2.46 | 1.135 | TI-1F-UZ-D | E00 | 78 | no | - | 0 | E00-010-001-78 | Ja | DD | - | BGS | 1115Rau0000005181 | 1113Mak0812435731 | 200 | no | AllplanAttributes (SMT) - ash T_Strahlenschutz: 0.000000; ash T_Anschlag Gangflügel: -; Positionsnummer_Text: S68
SMT | H2 Ebene 0 | 2.46 | 1.01 | TI-1F-UZ-ZK | E00 | 50 | yes | - | 0 | E00-033-001-50 | Ja | DK | 27 dB | BS | 1116Rau0000066656 | 1113Mak0813517673 | 200 | no | AllplanAttributes (SMT) - ash T_Strahlenschutz: 0.000000; ash T_Anschlag Gangflügel: -; Positionsnummer_Text: S68
SMT | H2 Ebene 0 | 2.46 | 1.01 | TI-1F-UZ-ZK | E00 | 129 | yes | - | 0 | E00-084-001-129 | Ja | DK | 27 dB | BS | 1116Rau0000066737 | 1113Mak0814015600 | 200 | no | AllplanAttributes (SMT) - ash T_Strahlenschutz: 0.000000; ash T_Anschlag Gangflügel: -; Positionsnummer_Text: S68
SMT | H2 Ebene 0 | 2.46 | 1.01 | TI-1F-UZ-ZK | E00 | 48 | yes | - | 0 | E00-034-001-48 | Ja | DK | 27 dB | BS | 1116Rau0000066659 | 1113Mak0813516889 | 200 | no | AllplanAttributes (SMT) - ash T_Strahlenschutz: 0.000000; ash T_Anschlag Gangflügel: -; Positionsnummer_Text: S68
SMT | H2 Ebene 0 | 2.46 | 1.01 | TI-1F-UZ-ZK | E00 | 126 | yes | - | 0 | E00-085-001-126 | Ja | DK | 27 dB | BS | 1116Rau0000066731 | 1113Mak0814158376 | 200 | no | AllplanAttributes (SMT) - ash T_Strahlenschutz: 0.000000; ash T_Anschlag Gangflügel: -; Positionsnummer_Text: S68
SMT | H2 Ebene 0 | 2.46 | 1.01 | TI-1F-UZ-ZK | E00 | 124 | yes | - | 0 | E00-086-001-124 | Ja | DK | 27 dB | BS | 1116Rau0000066734 | 1113Mak0814158370 | 200 | no | AllplanAttributes (SMT) - ash T_Strahlenschutz: 0.000000; ash T_Anschlag Gangflügel: -; Positionsnummer_Text: S68
SMT | H2 Ebene 0 | 2.46 | 1.135 | TI-1F-UZ-ZK | E00 | 77 | no | OTS | 0 | E00-011-001-77 | - | DK | - | BS | 1116Rau0000066472 | 1113Mak0812447152 | 200 | yes | Pset_DoorCommon - FireRating: EI2 30; AllplanAttributes (SMT) - ash T_Strahlenschutz: 0.000000; ash T_Anschlag Gangflügel: -; Positionsnummer_Text: S68

# IfcDoor: SMT (11)
Type - PredefinedType: DOOR; OperationType: SINGLE_SWING_RIGHT; ParameterTakesPrecedence: no
Type - IfcDoorLiningProperties - LiningDepth: 0.352 m; LiningThickness: 0.04 m
AllplanAttributes (SMT) - Gewerk: Zimmer- und Holzbauarbeiten; V6: 0 m; V7: 0 m; V8: 0 m; V9: 0; Programmversion: 3.1; Objektname: Türmakro; Bezeichnung: SMT; Plugin_Bezeichnung: MainObject; Plugin_Objektname: SmartPartCompressed; Glasanteil_berücksichtigen: 100; Version: 7.21; ash T_Sichtschutz: -; ash R_Verweis Wandansicht: -; ash T_Zulage Schachttür: no; ash T_Panik: -; ash T_Zarge_Typ: UZ; ash T_Gewerk Los: -; ash T_Erforderl. Durchgangsbreite: 0 m; ash T_Türblatt sichtbar 2D: ja; ash T_Zusatzfunktion Panikschloss: -; ash T_Fluchtwegsicherung: -; ash T_Standflügel-Betätigung: -; ash T_Zusatzfunktion Türschließer: -; ash T_Türschließer-Montage: -; ash T_Feststellanlage (FSA): -; ash T_Zusätzliche Rauchmelder: -; ash T_Zusätzl. Anschluss an BMA: -; ash T_Impulsgeber: -; ash T_Sicherheits-Sensorleisten: -; ash T_Anschl. an Einbruchmeld.anl.: -; ash T_Klemmschutz: -; ash T_LV-Positions-Nr.: -; ash T_Plan-Nr.: -; ash T_Sonstiges, Bemerkungen: -; ash T_nicht abschließbar: no; ash T_Material Seitenteil: -; ash T_Kantengeometrie: 2F; ash T_Kantenmaterial: PU; ash T_Blatt_Oberfläche: HPL; ash T_Erford. Durgangshöhe: 0 m; ash T_Rammschutz: BL; ash T_Fluchtwegrichtung: -; ash T_Lüftungsgitter: 0 m2; ash T_Feuchtebeständigkeit: -; ash T_E_Öffner: -; ash T_Automatik_Antrieb: -; ash T_Sturz: -; ash T_Blatt_Material: HO; ash T_Schlossfunktion: -; ash T_Schliesszylinder: PZ; ash T_Glasausschnitt: -; ash T_Sonder_Wandmaterial: -; ash T_Anz_Reedkontakte: 0; ash T_Anz_Riegelkontakte: 0; ash T_Schallschutz: -; ash T_Zarge_Material: ST; ash T_Bodeneinstand: -; ash T_Blatt_Farbe: -; Attributset-Objekt: Door; Abrechnungsart: St
AllplanQuantities - GlassSurface: 0; HeightWindowSillOutside: 0; HeightWindowSillInside: 0; OffsetOpeningTop: 0; OffsetOpeningLeft: 0; OffsetOpeningRight: 0; DeductionOpeningBottom: 100; DeductionOpeningLeft: 40; DeductionOpeningRight: 40; DeductionOpeningTop: 40
Pset_DoorCommon - Status: NEW; IsExternal: no; ThermalTransmittance: 0 W/K/m2; HandicapAccessible: no; FireExit: no
Name | In | OverallHeight (m) | OverallWidth (m) | Material = AllplanAttributes (SMT), Material | Ortscode_Geschoßbezeichnung | Text1 | ash T_Dichtschließend | ash T_Türschließer | OKFF | ash T_Bodentürstopper | ash T_Tür-Nr. | ash T_Anschlag Gangflügel | ash T_Bodendichtung | ash T_Beschlag | ash T_Raum zugehörigkeit | P_ID | Allright_Bauteil_ID | OffsetOpeningBottom | FireRating | SmokeStop = SelfClosing | ash T_Strahlenschutz | Positionsnummer_Text
SMT | H2 Ebene +2 | 2.41 | 1.135 | TI-1F-UZ-D | E02 | 99 | no | OTS | 7.5 | - | E02-059-002-99 | - | - | DD | BS | 1216Rau0000046973 | 1213Mak0813004244 | 150 | EI2 30 | yes
SMT | H2 Ebene +2 | 2.41 | 1.135 | TI-1F-UZ-D | E02 | 97 | no | - | 7.5 | - | E02-066-001-97 |  | Ja | DD | BGS | 1215Rau0000006941 | 1213Mak0813004478 | 150 |  | no
SMT | H2 Ebene +2 | 2.41 | 1.01 | TI-1F-UZ-D | E02 | 79 | yes | - | 7.5 | W | E02-009-001-79 |  | Ja | DK | BS | 1216Rau0000046525 | 1213Mak0813004750 | 150 | - | no
SMT | H2 Ebene +2 | 2.41 | 1.135 | TI-1F-UZ-D | E02 | 78 | no | - | 7.5 | - | E02-010-001-78 |  | Ja | DD | BGS | 1215Rau0000006920 | 1213Mak0813004745 | 150 |  | no
SMT | H2 Ebene +2 | 2.41 | 1.01 | TI-1F-UZ-D | E02 | 96 | yes | - | 7.5 | - | E02-067-001-96 |  | Ja | DK | BS | 1216Rau0000047169 | 1213Mak0813004483 | 150 | - | no
SMT | H2 Ebene +1 | 2.41 | 1.01 | TI-1F-UZ-ZK | E01 | 96 | yes | - | 3.75 | - | E01-067-001-96 | - | Ja | DK | BS | 1166Rau0000034261 | 1163Mak0812774567 | 150 | - | no | 0.000000 | U100
SMT | H2 Ebene +1 | 2.41 | 1.135 | TI-1F-UZ-D | E01 | 78 | no | - | 3.75 | - | E01-010-001-78 | - | Ja | DD | BGS | 1165Rau0000004808 | 1163Mak0812435731 | 150 |  | no | 0.000000 | U100
SMT | H2 Ebene +1 | 2.41 | 1.135 | TI-1F-UZ-ZK | E01 | 77 | no | OTS | 3.75 | - | E01-011-001-77 | - | - | DK | BS | 1166Rau0000033220 | 1163Mak0812447152 | 150 | EI2 30 | yes | 0.000000 | U100
SMT | H2 Ebene +1 | 2.41 | 1.135 | TI-1F-UZ-D | E01 | 99 | no | OTS | 3.75 | - | E01-059-002-99 | - | - | DD | BS | 1166Rau0000034137 | 1163Mak0812523473 | 150 | EI2 30 | yes | 0.000000 | U100
SMT | H2 Ebene 0 | 2.46 | 1.135 | TI-1F-UZ-D | E00 | 99 | no | OTS | 0 | - | E00-059-002-99 | - | - | DD | BS | 1115Rau0000005201 | 1113Mak0812523473 | 200 | EI2 30 | yes | 0.000000 | S68
SMT | H2 Ebene 0 | 2.46 | 1.01 | TI-1F-UZ-ZK | E00 | 96 | yes | - | 0 | - | E00-067-001-96 | - | Ja | DK | BS | 1116Rau0000066544 | 1113Mak0814242351 | 200 | - | no | 0.000000 | S68

# IfcDoor: SMT (3)
Type - PredefinedType: DOOR; OperationType: SINGLE_SWING_RIGHT; ParameterTakesPrecedence: no
Type - IfcDoorLiningProperties - LiningDepth: 0.36 m; LiningThickness: 0.04 m
Material: TI-1F-UZ-D
AllplanAttributes (SMT) - Gewerk: Metallbau-, Schlosserarbeiten; V6: 0 m; V7: 0 m; V8: 0 m; V9: 0; Programmversion: 3.1; Objektname: Türmakro; Bezeichnung: SMT; Material: TI-1F-UZ-D; Plugin_Bezeichnung: MainObject; Plugin_Objektname: SmartPartCompressed; Glasanteil_berücksichtigen: 100; Version: 7.21; ash T_Zulage Schachttür: no; ash T_Dichtschließend: no; ash T_Zarge_Typ: UZ; ash T_Türschließer: OTS; ash T_Erforderl. Durchgangsbreite: 0 m; ash T_Türblatt sichtbar 2D: ja; ash T_Feststellanlage (FSA): -; ash T_nicht abschließbar: no; ash T_Erford. Durgangshöhe: 0 m; ash T_Anschlag Gangflügel: -; ash T_Lüftungsgitter: 0 m2; ash T_Schliesszylinder: PZ; ash T_Beschlag: KD; ash T_Anz_Reedkontakte: 0; ash T_Anz_Riegelkontakte: 0; ash T_Schallschutz: -; ash T_Zarge_Material: ST; ash T_Raum zugehörigkeit: BGS; Attributset-Objekt: Door; Abrechnungsart: St
AllplanQuantities - GlassSurface: 0; HeightWindowSillOutside: 0; HeightWindowSillInside: 0; OffsetOpeningTop: 0; OffsetOpeningLeft: 0; OffsetOpeningRight: 0; DeductionOpeningBottom: 100; DeductionOpeningLeft: 40; DeductionOpeningRight: 40; DeductionOpeningTop: 40
Pset_DoorCommon - Status: NEW; IsExternal: no; FireRating: EI2 30; ThermalTransmittance: 0 W/K/m2; HandicapAccessible: no; SmokeStop: yes; SelfClosing: yes; FireExit: no
Name | In | OverallHeight (m) | OverallWidth (m) | Ortscode_Geschoßbezeichnung | Text1 | OKFF | ash T_Strahlenschutz | ash T_Tür-Nr. | ash T_Kantengeometrie | ash T_Blatt_Oberfläche | ash T_Blatt_Material | P_ID | Allright_Bauteil_ID | OffsetOpeningBottom | ash T_Sichtschutz = ash R_Verweis Wandansicht = ash T_Panik = ash T_Gewerk Los = ash T_Zusatzfunktion Panikschloss = ash T_Fluchtwegsicherung = ash T_Standflügel-Betätigung = ash T_Zusatzfunktion Türschließer = ash T_Türschließer-Montage = ash T_Zusätzliche Rauchmelder = ash T_Zusätzl. Anschluss an BMA = ash T_Impulsgeber = ash T_Sicherheits-Sensorleisten = ash T_Anschl. an Einbruchmeld.anl. = ash T_Klemmschutz = ash T_LV-Positions-Nr. = ash T_Plan-Nr. = ash T_Sonstiges, Bemerkungen = ash T_Bodentürstopper = ash T_Material Seitenteil = ash T_Fluchtwegrichtung = ash T_Bodendichtung = ash T_Feuchtebeständigkeit = ash T_E_Öffner = ash T_Automatik_Antrieb = ash T_Sturz = ash T_Schlossfunktion = ash T_Glasausschnitt = ash T_Sonder_Wandmaterial = ash T_Bodeneinstand = ash T_Blatt_Farbe | ash T_Kantenmaterial | ash T_Rammschutz
SMT | H2 Ebene +3 | 2.01 | 0.885 | E03 | 5 | 11.25 | 0.000000 | E03-A02-001-5 | LF | L | ST | 1266Rau0000012858 | 1263Mak0812750350 | 0 | AllplanAttributes (SMT) - Text2: -
SMT | H2 Ebene +2 | 2.41 | 0.76 | E02 | 18 | 7.5 |  | E02-S01-001-18 | 2F | HPL | HO | 1215Rau0000006938 | 1213Mak0813005138 | 150 | - | PU | BL
SMT | H2 Ebene 0 | 2.46 | 0.76 | E00 | 18 | 0 | 0.000000 | E00-S01-001-18 | 2F | HPL | HO | 1115Rau0000005163 | 1113Mak0813453129 | 380 | - | PU | BL | AllplanAttributes (SMT) - ash T_Laserschutz: -; Positionsnummer_Text: S68

# IfcDoor: SMT (8)
Type - PredefinedType: DOOR; OperationType: SINGLE_SWING_RIGHT; ParameterTakesPrecedence: no
Type - IfcDoorLiningProperties - LiningDepth: 0.395 m; LiningThickness: 0.04 m
OverallWidth: 1.01 m; Material: TI-1F-UZ-D
AllplanAttributes (SMT) - Gewerk: Zimmer- und Holzbauarbeiten; V6: 0 m; V7: 0 m; V8: 0 m; V9: 0; Programmversion: 3.1; Bezeichnung: SMT; Material: TI-1F-UZ-D; Plugin_Bezeichnung: MainObject; Plugin_Objektname: SmartPartCompressed; Glasanteil_berücksichtigen: 100; Version: 7.21; ash T_Sichtschutz: -; ash R_Verweis Wandansicht: -; ash T_Zulage Schachttür: no; ash T_Panik: -; ash T_Zarge_Typ: UZ; ash T_Gewerk Los: -; ash T_Erforderl. Durchgangsbreite: 0 m; ash T_Türblatt sichtbar 2D: ja; ash T_Zusatzfunktion Panikschloss: -; ash T_Fluchtwegsicherung: -; ash T_Standflügel-Betätigung: -; ash T_Zusatzfunktion Türschließer: -; ash T_Türschließer-Montage: -; ash T_Feststellanlage (FSA): -; ash T_Zusätzliche Rauchmelder: -; ash T_Zusätzl. Anschluss an BMA: -; ash T_Impulsgeber: -; ash T_Sicherheits-Sensorleisten: -; ash T_Anschl. an Zuttrittskontrolle: -; ash T_Anschl. an Einbruchmeld.anl.: -; ash T_Klemmschutz: -; ash T_LV-Positions-Nr.: -; ash T_Plan-Nr.: -; ash T_Sonstiges, Bemerkungen: -; ash T_Bodentürstopper: -; ash T_nicht abschließbar: no; ash T_Material Seitenteil: -; ash T_Kantengeometrie: 2F; ash T_Kantenmaterial: PU; ash T_Blatt_Oberfläche: HPL; ash T_Erford. Durgangshöhe: 0 m; ash T_Rammschutz: BL; ash T_Fluchtwegrichtung: -; ash T_Lüftungsgitter: 0 m2; ash T_Feuchtebeständigkeit: -; ash T_E_Öffner: -; ash T_Automatik_Antrieb: -; ash T_Sturz: -; ash T_Blatt_Material: HO; ash T_Schlossfunktion: -; ash T_Glasausschnitt: -; ash T_Sonder_Wandmaterial: -; ash T_Anz_Reedkontakte: 0; ash T_Anz_Riegelkontakte: 0; ash T_Zarge_Material: ST; ash T_Bodeneinstand: -; ash T_Blatt_Farbe: -; Attributset-Objekt: Door; Abrechnungsart: St
AllplanQuantities - GlassSurface: 0; HeightWindowSillOutside: 0; HeightWindowSillInside: 0; OffsetOpeningTop: 0; OffsetOpeningLeft: 0; OffsetOpeningRight: 0; DeductionOpeningBottom: 100; DeductionOpeningLeft: 40; DeductionOpeningRight: 40; DeductionOpeningTop: 40
Pset_DoorCommon - Status: NEW; IsExternal: no; ThermalTransmittance: 0 W/K/m2; FireExit: no
Name | In | OverallHeight (m) | Ortscode_Geschoßbezeichnung | Objektname | Text1 | ash T_Dichtschließend | ash T_Türschließer | OKFF | ash T_Tür-Nr. | ash T_Bodendichtung | ash T_Schliesszylinder | ash T_Beschlag | ash T_Schallschutz | ash T_Raum zugehörigkeit | P_ID | Allright_Bauteil_ID | OffsetOpeningBottom | FireRating | HandicapAccessible | SmokeStop = SelfClosing | Codetext = Reference | Tragendes Bauteil | Typ = Brandverhalten = AcousticRating | Brennbares Material = Brandabschnittsdefinierendes Bauteil | Brandschutzklasse | ash T_Strahlenschutz | ash T_Anschlag Gangflügel | Positionsnummer_Text
SMT | H2 Ebene +2 | 2.41 | E02 | Türmakro | 161 | yes | - | 7.5 | E02-062-001-161 | - | WC | DD | - | BGS | 1215Rau0000006941 | 1213Mak0813005413 | 150 | - | no | no
SMT | H2 Ebene +2 | 2.41 | E02 | Türmakro, -SmartPart | 160 | no | OTS | 7.5 | E02-061-001-160 | Ja | PZ | DK | 27 dB | BS | 1216Rau0000046767 | 1213Mak0813005321 | 150 | EI2 60 | no | yes | Codetext | yes | 0 | no | A | 0.000000 | -
SMT | H2 Ebene +2 | 2.41 | E02 | Türmakro, -SmartPart | 159 | no | OTS | 7.5 | E02-060-001-159 | Ja | PZ | KD | 27 dB | BGS | 1215Rau0000006941 | 1213Mak0813005327 | 150 | EI2 60 | no | yes | Codetext | yes | 0 | no | A | 0.000000 | -
SMT | H2 Ebene +1 | 2.41 | E01 | Türmakro, -SmartPart | 160 | no | OTS | 3.75 | E01-061-001-160 | Ja | PZ | DK | 27 dB | BS | 1166Rau0000034163 | 1163Mak0812553649 | 150 | EI2 60 | no | yes | Codetext | yes | 0 | no | A | 0.000000 | - | U100
SMT | H2 Ebene +1 | 2.41 | E01 | Türmakro, -SmartPart | 159 | no | OTS | 3.75 | E01-060-001-159 | Ja | PZ | KD | 27 dB | BGS | 1165Rau0000004819 | 1163Mak0812553541 | 150 | EI2 60 | no | yes | Codetext | yes | 0 | no | A | 0.000000 | - | U100
SMT | H2 Ebene 0 | 2.46 | E00 | Türmakro, -SmartPart | 159 | no | OTS | 0 | E00-060-001-159 | Ja | PZ | KD | 27 dB | BGS | 1115Rau0000005220 | 1113Mak0812553541 | 200 | EI2 60 | no | yes | Codetext | yes | 0 | no | A | 0.000000 | - | S68 | AllplanAttributes (SMT) - ash T_Laserschutz: -
SMT | H2 Ebene 0 | 2.46 | E00 | Türmakro, -SmartPart | 160 | no | OTS | 0 | E00-061-001-160 | Ja | PZ | DK | 27 | BS | 1116Rau0000066520 | 1113Mak0812553649 | 200 | EI2 60 | no | yes | Codetext | yes | 0 | no | A | 0.000000 | - | S68 | AllplanAttributes (SMT) - ash T_Laserschutz: -
SMT | H2 Ebene 0 | 2.46 | E00 | Türmakro, -SmartPart | 161 | no | - | 0 | E00-062-001-161 | - | WC | DD | 27 | BS | 1116Rau0000066520 | 1113Mak0813946561 | 200 | - | yes | no | Codetext | yes | 0 | no | A | 0.000000 | - | S68 | AllplanAttributes (SMT) - ash T_Laserschutz: -

# IfcDoor: SMT (3)
Type - PredefinedType: DOOR; OperationType: SLIDING_TO_LEFT; ParameterTakesPrecedence: no
OverallHeight: 2.41 m; OverallWidth: 1.26 m; Material: TI-1F-UZ-ZK
AllplanAttributes (SMT) - Gewerk: Metallbau-, Schlosserarbeiten; V6: 0 m; V7: 0 m; V8: 0 m; V9: 0; Programmversion: 2.2; Objektname: Makro Laufwerkskasten; Bezeichnung: SMT; Plugin_Bezeichnung: MainObject; Plugin_Objektname: SmartPartCompressed; Version: 1.0; Abrechnungsart: St; Text1: 104; Material: TI-1F-UZ-ZK; Glasanteil_berücksichtigen: 100; ash T_Sichtschutz: -; ash R_Verweis Wandansicht: -; ash T_Zulage Schachttür: no; ash T_Dichtschließend: no; ash T_Panik: -; ash T_Zarge_Typ: -; ash T_Türschließer: -; ash T_Gewerk Los: -; ash T_Erforderl. Durchgangsbreite: 0 m; ash T_Türblatt sichtbar 2D: ja; ash T_Zusatzfunktion Panikschloss: -; ash T_Fluchtwegsicherung: -; ash T_Standflügel-Betätigung: -; ash T_Zusatzfunktion Türschließer: -; ash T_Türschließer-Montage: -; ash T_Feststellanlage (FSA): -; ash T_Zusätzliche Rauchmelder: -; ash T_Zusätzl. Anschluss an BMA: -; ash T_Impulsgeber: -; ash T_Sicherheits-Sensorleisten: -; ash T_Anschl. an Zuttrittskontrolle: -; ash T_Anschl. an Einbruchmeld.anl.: -; ash T_Klemmschutz: -; ash T_LV-Positions-Nr.: -; ash T_Plan-Nr.: -; ash T_Sonstiges, Bemerkungen: -; ash T_Bodentürstopper: -; ash T_nicht abschließbar: no; ash T_Material Seitenteil: -; ash T_Strahlenschutz: 0.000000; ash T_Kantengeometrie: -; ash T_Kantenmaterial: -; ash T_Blatt_Oberfläche: L; ash T_Erford. Durgangshöhe: 0 m; ash T_Laserschutz: -; ash T_Rammschutz: -; ash T_Fluchtwegrichtung: -; ash T_Anschlag Gangflügel: -; ash T_Bodendichtung: -; ash T_Lüftungsgitter: 0 m2; ash T_Feuchtebeständigkeit: -; ash T_E_Öffner: -; ash T_Automatik_Antrieb: -; ash T_Sturz: -; ash T_Blatt_Material: SG; ash T_Schlossfunktion: -; ash T_Schliesszylinder: PZ; ash T_Beschlag: KD; ash T_Glasausschnitt: -; ash T_Sonder_Wandmaterial: -; ash T_Anz_Reedkontakte: 0; ash T_Anz_Riegelkontakte: 0; ash T_Schallschutz: 37 dB; ash T_Zarge_Material: -; ash T_Bodeneinstand: -; ash T_Raum zugehörigkeit: BGS; ash T_Blatt_Farbe: -; Attributset-Objekt: Door; P_ID: 1166Rau0000034222
AllplanAttributes (TGR 1.5) - Codetext: Typ; V6: 0 m; V7: 0 m; V8: 0 m; V9: 0; Programmversion: 3.1; Objektname: TGR-Makro; Text1: PlanNo.; Bezeichnung: TGR 1.5; Plugin_Bezeichnung: MainObject; Plugin_Objektname: SmartPartCompressed; Gesamtlänge: 12.3825; Version: 1.5; ash T_Türprofilnummer: 3; Positionsnummer_Text: U100; P_ID: 1166Rau0000034222; Abrechnungsart: St
AllplanQuantities - GlassSurface: 0; HeightWindowSillOutside: 0; HeightWindowSillInside: 0; OffsetOpeningTop: 0; OffsetOpeningLeft: 0; OffsetOpeningRight: 0; DeductionOpeningBottom: 100; DeductionOpeningLeft: 20; DeductionOpeningRight: 20; DeductionOpeningTop: 25
Pset_DoorCommon - Status: NEW; IsExternal: no; ThermalTransmittance: 0 W/K/m2; HandicapAccessible: no; SmokeStop: no; SelfClosing: no; FireExit: no
Name | In | AllplanAttributes (SMT), Ortscode_Geschoßbezeichnung | AllplanAttributes (SMT), OKFF | AllplanAttributes (SMT), Allright_Bauteil_ID | ash T_Tür-Nr. | AllplanAttributes (TGR 1.5), Allright_Bauteil_ID | OffsetOpeningBottom | SecurityRating
SMT | H2 Ebene +2 | E02 | 7.5 | 1213Mak0813547063 | E01-063-002-104 | 1213Mak0813547066 | 150 | SA | AllplanAttributes (TGR 1.5) - Ortscode_Geschoßbezeichnung: E02; OKFF: 7.5
SMT | H2 Ebene +1 | E01 | 3.75 | 1163Mak0814706073 | E01-063-002-104 | 1163Mak0814706075 | 100 | SA
SMT | H2 Ebene 0 | E01 | 3.75 | 1113Mak0814194335 | E00-063-002-104 | 1113Mak0814187811 | 100

# IfcDoor: SMT (3)
Type - PredefinedType: DOOR; OperationType: SLIDING_TO_RIGHT; ParameterTakesPrecedence: no
OverallHeight: 2.41 m; OverallWidth: 1.26 m; Material: TI-1F-UZ-ZK
AllplanAttributes (SMT) - Gewerk: Metallbau-, Schlosserarbeiten; V6: 0 m; V7: 0 m; V8: 0 m; V9: 0; Programmversion: 2.2; Objektname: Makro Laufwerkskasten; Bezeichnung: SMT; Plugin_Bezeichnung: MainObject; Plugin_Objektname: SmartPartCompressed; Version: 1.0; Abrechnungsart: St; Text1: 70; Material: TI-1F-UZ-ZK; Glasanteil_berücksichtigen: 100; ash T_Sichtschutz: -; ash R_Verweis Wandansicht: -; ash T_Zulage Schachttür: no; ash T_Dichtschließend: no; ash T_Panik: -; ash T_Zarge_Typ: -; ash T_Türschließer: -; ash T_Gewerk Los: -; ash T_Erforderl. Durchgangsbreite: 0 m; ash T_Türblatt sichtbar 2D: ja; ash T_Zusatzfunktion Panikschloss: -; ash T_Fluchtwegsicherung: -; ash T_Standflügel-Betätigung: -; ash T_Zusatzfunktion Türschließer: -; ash T_Türschließer-Montage: -; ash T_Feststellanlage (FSA): -; ash T_Zusätzliche Rauchmelder: -; ash T_Zusätzl. Anschluss an BMA: -; ash T_Impulsgeber: -; ash T_Sicherheits-Sensorleisten: -; ash T_Anschl. an Zuttrittskontrolle: -; ash T_Anschl. an Einbruchmeld.anl.: -; ash T_Klemmschutz: -; ash T_LV-Positions-Nr.: -; ash T_Plan-Nr.: -; ash T_Sonstiges, Bemerkungen: -; ash T_Bodentürstopper: -; ash T_nicht abschließbar: no; ash T_Material Seitenteil: -; ash T_Strahlenschutz: 0.000000; ash T_Kantengeometrie: -; ash T_Kantenmaterial: -; ash T_Blatt_Oberfläche: L; ash T_Erford. Durgangshöhe: 0 m; ash T_Laserschutz: -; ash T_Rammschutz: -; ash T_Fluchtwegrichtung: -; ash T_Anschlag Gangflügel: -; ash T_Bodendichtung: -; ash T_Lüftungsgitter: 0 m2; ash T_Feuchtebeständigkeit: -; ash T_E_Öffner: -; ash T_Automatik_Antrieb: -; ash T_Sturz: -; ash T_Blatt_Material: SG; ash T_Schlossfunktion: -; ash T_Schliesszylinder: PZ; ash T_Beschlag: KD; ash T_Glasausschnitt: -; ash T_Sonder_Wandmaterial: -; ash T_Anz_Reedkontakte: 0; ash T_Anz_Riegelkontakte: 0; ash T_Schallschutz: 37 dB; ash T_Zarge_Material: -; ash T_Bodeneinstand: -; ash T_Raum zugehörigkeit: BGS; ash T_Blatt_Farbe: -; Attributset-Objekt: Door; P_ID: 1166Rau0000034222
AllplanAttributes (TGR 1.5) - Codetext: Typ; V6: 0 m; V7: 0 m; V8: 0 m; V9: 0; Programmversion: 3.1; Objektname: TGR-Makro; Text1: PlanNo.; Bezeichnung: TGR 1.5; Plugin_Bezeichnung: MainObject; Plugin_Objektname: SmartPartCompressed; Gesamtlänge: 12.3825; Version: 1.5; ash T_Türprofilnummer: 3; Positionsnummer_Text: U100; P_ID: 1166Rau0000034222; Abrechnungsart: St
AllplanQuantities - GlassSurface: 0; HeightWindowSillOutside: 0; HeightWindowSillInside: 0; OffsetOpeningTop: 0; OffsetOpeningLeft: 0; OffsetOpeningRight: 0; DeductionOpeningBottom: 100; DeductionOpeningLeft: 20; DeductionOpeningRight: 20; DeductionOpeningTop: 25
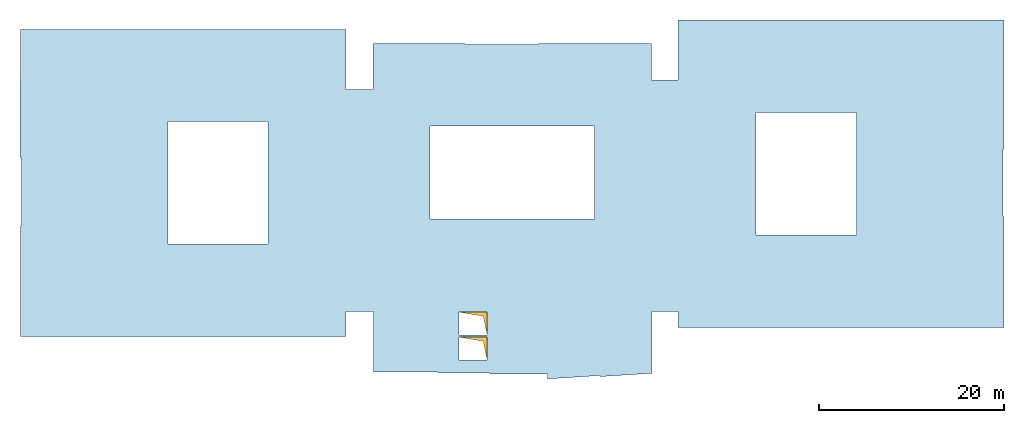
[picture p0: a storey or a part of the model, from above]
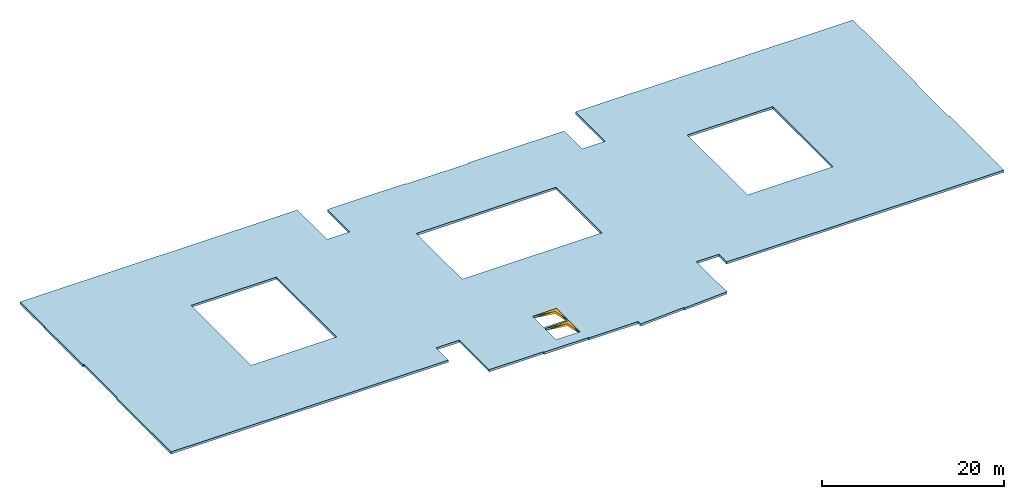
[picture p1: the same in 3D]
Properties of the parts of a building model (IFC4), part 28 of 80

# IfcDoor: SMT (3)
Pset_DoorCommon - Status: NEW; IsExternal: no; ThermalTransmittance: 0 W/K/m2; HandicapAccessible: no; SmokeStop: no; SelfClosing: no; FireExit: no; SecurityRating: SA
Name | In | AllplanAttributes (SMT), Ortscode_Geschoßbezeichnung | AllplanAttributes (SMT), OKFF | AllplanAttributes (SMT), Allright_Bauteil_ID | ash T_Tür-Nr. | AllplanAttributes (TGR 1.5), Allright_Bauteil_ID | OffsetOpeningBottom
SMT | H2 Ebene +2 | E02 | 7.5 | 1213Mak0813546225 | E01-013-002-70 | 1213Mak0813546221 | 150 | AllplanAttributes (TGR 1.5) - Ortscode_Geschoßbezeichnung: E02; OKFF: 7.5
SMT | H2 Ebene +1 | E01 | 3.75 | 1163Mak0814705824 | E01-013-002-70 | 1163Mak0814705823 | 100
SMT | H2 Ebene 0 | E01 | 3.75 | 1113Mak0814194996 | E00-013-002-70 | 1113Mak0814194993 | 100

# IfcDoor: SMT
In: H2 Ebene +2
Type - PredefinedType: DOOR; OperationType: SLIDING_TO_RIGHT; ParameterTakesPrecedence: no
Type - IfcDoorLiningProperties - LiningDepth: 0.07 m; LiningThickness: 0.04 m
OverallHeight: 2.41 m; OverallWidth: 1.01 m; Material: TI-1F-UZ-D
AllplanAttributes (SMT) - Gewerk: Metallbau-, Schlosserarbeiten; V6: 0 m; V7: 0 m; V8: 0 m; V9: 0; Ortscode_Geschoßbezeichnung: E02; Programmversion: 2.2; Objektname: Makro Laufwerkskasten; Bezeichnung: SMT; Plugin_Bezeichnung: MainObject; Plugin_Objektname: SmartPartCompressed; Version: 1.0; OKFF: 7.5; Allright_Bauteil_ID: 1213Mak0813407566; Abrechnungsart: St; Text1: 155; Material: TI-1F-UZ-D; Glasanteil_berücksichtigen: 100; ash T_Sichtschutz: -; ash R_Verweis Wandansicht: -; ash T_Zulage Schachttür: no; ash T_Dichtschließend: no; ash T_Panik: -; ash T_Zarge_Typ: UZ; ash T_Türschließer: -; ash T_Gewerk Los: -; ash T_Erforderl. Durchgangsbreite: 0 m; ash T_Türblatt sichtbar 2D: ja; ash T_Zusatzfunktion Panikschloss: -; ash T_Fluchtwegsicherung: -; ash T_Standflügel-Betätigung: -; ash T_Zusatzfunktion Türschließer: -; ash T_Türschließer-Montage: -; ash T_Feststellanlage (FSA): -; ash T_Zusätzliche Rauchmelder: -; ash T_Zusätzl. Anschluss an BMA: -; ash T_Impulsgeber: -; ash T_Sicherheits-Sensorleisten: -; ash T_Anschl. an Einbruchmeld.anl.: -; ash T_Klemmschutz: -; ash T_LV-Positions-Nr.: -; ash T_Plan-Nr.: -; ash T_Sonstiges, Bemerkungen: -; ash T_Bodentürstopper: -; ash T_nicht abschließbar: no; ash T_Material Seitenteil: -; ash T_Tür-Nr.: E02-064-002-155; ash T_Kantengeometrie: -; ash T_Kantenmaterial: PU; ash T_Blatt_Oberfläche: HPL; ash T_Erford. Durgangshöhe: 0 m; ash T_Rammschutz: BL; ash T_Fluchtwegrichtung: -; ash T_Bodendichtung: -; ash T_Lüftungsgitter: 0 m2; ash T_Feuchtebeständigkeit: -; ash T_E_Öffner: -; ash T_Automatik_Antrieb: -; ash T_Sturz: -; ash T_Blatt_Material: HO; ash T_Schlossfunktion: -; ash T_Schliesszylinder: PZ; ash T_Beschlag: KD; ash T_Glasausschnitt: -; ash T_Sonder_Wandmaterial: -; ash T_Anz_Reedkontakte: 0; ash T_Anz_Riegelkontakte: 0; ash T_Schallschutz: 37 dB; ash T_Zarge_Material: ST; ash T_Bodeneinstand: -; ash T_Raum zugehörigkeit: BGS; ash T_Blatt_Farbe: -; Attributset-Objekt: Door; P_ID: 1216Rau0000046869
AllplanQuantities - OffsetOpeningBottom: 150; GlassSurface: 0; HeightWindowSillOutside: 0; HeightWindowSillInside: 0; OffsetOpeningTop: 0; OffsetOpeningLeft: 0; OffsetOpeningRight: 0; DeductionOpeningBottom: 100; DeductionOpeningLeft: 40; DeductionOpeningRight: 40; DeductionOpeningTop: 40
Pset_DoorCommon - Status: NEW; IsExternal: no; ThermalTransmittance: 0 W/K/m2; HandicapAccessible: no; SmokeStop: no; SelfClosing: no; FireExit: no

# IfcDoor: SMT (5)
Type - PredefinedType: DOOR; OperationType: SLIDING_TO_RIGHT; ParameterTakesPrecedence: no
Type - IfcDoorLiningProperties - LiningDepth: 0.302 m; LiningThickness: 0.04 m
OverallWidth: 1.01 m
AllplanAttributes (SMT) - Gewerk: Zimmer- und Holzbauarbeiten; V6: 0 m; V7: 0 m; V8: 0 m; V9: 0; Programmversion: 3.1; Objektname: Türmakro; Bezeichnung: SMT; Plugin_Bezeichnung: MainObject; Plugin_Objektname: SmartPartCompressed; Glasanteil_berücksichtigen: 100; Version: 7.21; ash T_Sichtschutz: -; ash R_Verweis Wandansicht: -; ash T_Zulage Schachttür: no; ash T_Dichtschließend: no; ash T_Panik: -; ash T_Zarge_Typ: UZ; ash T_Türschließer: -; ash T_Gewerk Los: -; ash T_Erforderl. Durchgangsbreite: 0 m; ash T_Türblatt sichtbar 2D: ja; ash T_Zusatzfunktion Panikschloss: -; ash T_Fluchtwegsicherung: -; ash T_Standflügel-Betätigung: -; ash T_Zusatzfunktion Türschließer: -; ash T_Türschließer-Montage: -; ash T_Feststellanlage (FSA): -; ash T_Zusätzliche Rauchmelder: -; ash T_Zusätzl. Anschluss an BMA: -; ash T_Impulsgeber: -; ash T_Sicherheits-Sensorleisten: -; ash T_Anschl. an Einbruchmeld.anl.: -; ash T_Klemmschutz: -; ash T_LV-Positions-Nr.: -; ash T_Plan-Nr.: -; ash T_Sonstiges, Bemerkungen: -; ash T_Bodentürstopper: -; ash T_nicht abschließbar: no; ash T_Material Seitenteil: -; ash T_Kantengeometrie: -; ash T_Kantenmaterial: PU; ash T_Blatt_Oberfläche: HPL; ash T_Erford. Durgangshöhe: 0 m; ash T_Rammschutz: BL; ash T_Fluchtwegrichtung: -; ash T_Bodendichtung: -; ash T_Lüftungsgitter: 0 m2; ash T_Feuchtebeständigkeit: -; ash T_E_Öffner: -; ash T_Automatik_Antrieb: -; ash T_Sturz: -; ash T_Blatt_Material: HO; ash T_Schlossfunktion: -; ash T_Schliesszylinder: PZ; ash T_Beschlag: KD; ash T_Glasausschnitt: -; ash T_Sonder_Wandmaterial: -; ash T_Anz_Reedkontakte: 0; ash T_Anz_Riegelkontakte: 0; ash T_Schallschutz: 37 dB; ash T_Zarge_Material: ST; ash T_Bodeneinstand: -; ash T_Raum zugehörigkeit: BGS; ash T_Blatt_Farbe: -; Attributset-Objekt: Door; Abrechnungsart: St
AllplanQuantities - GlassSurface: 0; HeightWindowSillOutside: 0; HeightWindowSillInside: 0; OffsetOpeningTop: 0; OffsetOpeningLeft: 0; OffsetOpeningRight: 0; DeductionOpeningBottom: 100; DeductionOpeningLeft: 40; DeductionOpeningRight: 40; DeductionOpeningTop: 40
Pset_DoorCommon - Status: NEW; IsExternal: no; ThermalTransmittance: 0 W/K/m2; HandicapAccessible: no; SmokeStop: no; SelfClosing: no; FireExit: no
Name | In | OverallHeight (m) | Material = AllplanAttributes (SMT), Material | Ortscode_Geschoßbezeichnung | Text1 | OKFF | ash T_Tür-Nr. | P_ID | Allright_Bauteil_ID | OffsetOpeningBottom | ash T_Strahlenschutz | ash T_Anschlag Gangflügel | Positionsnummer_Text
SMT | H2 Ebene +2 | 2.41 | TI-1F-UZ-D | E02 | 168 | 7.5 | E02-012-002-168 | 1216Rau0000046869 | 1213Mak0813004088 | 150
SMT | H2 Ebene +1 | 2.41 | TI-1F-UZ-ZK | E01 | 168 | 3.75 | E01-012-002-168 | 1166Rau0000034222 | 1163Mak0812447069 | 150 | 0.000000 | - | U100 | AllplanAttributes (SMT) - ash T_Unterschnitt: -; ash T_Anschl. an Zuttrittskontrolle: -
SMT | H2 Ebene +1 | 2.41 | TI-1F-UZ-ZK | E01 | 155 | 3.75 | E01-064-002-155 | 1166Rau0000034222 | 1163Mak0812447068 | 150 | 0.000000 | - | U100
SMT | H2 Ebene 0 | 2.46 | TI-1F-UZ-ZK | E00 | 155 | 0 | E00-064-002-155 | 1116Rau0000066600 | 1113Mak0812447068 | 200 | 0.000000 | - | S68
SMT | H2 Ebene 0 | 2.46 | TI-1F-UZ-ZK | E00 | 168 | 0 | E00-012-001-168 | 1116Rau0000066612 | 1113Mak0812447069 | 200 | 0.000000 | - | S68

# IfcDoor: SMT (18)
Type - PredefinedType: DOOR; ParameterTakesPrecedence: no
AllplanAttributes (SMT) - V6: 0 m; V7: 0 m; V8: 0 m; V9: 0; Bezeichnung: SMT; Plugin_Bezeichnung: MainObject; Abrechnungsart: St
Name | In | OverallHeight (m) | OverallWidth (m) | Material = AllplanAttributes (SMT), Material | Gewerk | AllplanAttributes (SMT), Ortscode_Geschoßbezeichnung | AllplanAttributes (SMT), Objektname | AllplanAttributes (SMT), Text1 | Text2 | Glasanteil_berücksichtigen | ash T_Zulage Schachttür = ash T_Dichtschließend = ash T_nicht abschließbar = IsExternal = HandicapAccessible | ash T_Zarge_Typ | ash T_Türschließer | ash T_Erforderl. Durchgangsbreite (m) = ash T_Erford. Durgangshöhe (m) = ash T_Lüftungsgitter (m2) = ash T_Anz_Reedkontakte = OffsetOpeningTop = OffsetOpeningLeft = OffsetOpeningRight = ThermalTransmittance (W/K/m2) | ash T_Türblatt sichtbar 2D | AllplanAttributes (SMT), OKFF | ash T_Strahlenschutz | ash T_Tür-Nr. | ash T_Kantengeometrie | ash T_Blatt_Oberfläche | ash T_Anschlag Gangflügel = ash T_Schallschutz | ash T_Blatt_Material | ash T_Schliesszylinder | ash T_Beschlag | ash T_Anz_Riegelkontakte | ash T_Zarge_Material | ash T_Raum zugehörigkeit | Attributset-Objekt | AllplanAttributes (SMT), P_ID | AllplanAttributes (SMT), Allright_Bauteil_ID | OffsetOpeningBottom | Status | FireRating | SmokeStop = SelfClosing | FireExit | AllplanAttributes (SMT), Programmversion | AllplanAttributes (SMT), Plugin_Objektname | AllplanAttributes (SMT), Version | AllplanAttributes (SMT), Text4 | ash T_Sichtschutz = ash R_Verweis Wandansicht = ash T_Gewerk Los = ash T_Standflügel-Betätigung = ash T_Zusatzfunktion Türschließer = ash T_Türschließer-Montage = ash T_Zusätzliche Rauchmelder = ash T_Zusätzl. Anschluss an BMA = ash T_Impulsgeber = ash T_Sicherheits-Sensorleisten = ash T_Anschl. an Einbruchmeld.anl. = ash T_Klemmschutz = ash T_LV-Positions-Nr. = ash T_Plan-Nr. = ash T_Sonstiges, Bemerkungen = ash T_Bodentürstopper = ash T_Material Seitenteil = ash T_Kantenmaterial = ash T_Bodendichtung = ash T_Feuchtebeständigkeit = ash T_Glasausschnitt = ash T_Sonder_Wandmaterial = ash T_Bodeneinstand = ash T_Blatt_Farbe | ash T_Panik | ash T_Zusatzfunktion Panikschloss | ash T_Fluchtwegsicherung | ash T_Feststellanlage (FSA) | ash T_Anschl. an Zuttrittskontrolle | ash T_Rammschutz | ash T_Fluchtwegrichtung | ash T_Automatik_Antrieb | ash T_Sturz | ash T_Schlossfunktion | ash T_Steuerung (BG) | ash T_Steuerung (BS) | AllplanAttributes (TGR 1.5), Codetext | V6 (m) = V7 (m) = V8 (m) = V9 = HeightWindowSillOutside = HeightWindowSillInside | AllplanAttributes (TGR 1.5), Programmversion | AllplanAttributes (TGR 1.5), Objektname | AllplanAttributes (TGR 1.5), Text1 | Bezeichnung | Plugin_Bezeichnung | AllplanAttributes (TGR 1.5), Plugin_Objektname | Gesamtlänge | AllplanAttributes (TGR 1.5), Version | ash T_Türprofilnummer | AllplanAttributes (TGR 1.5), P_ID | AllplanAttributes (TGR 1.5), Allright_Bauteil_ID | Abrechnungsart | GlassSurface | DeductionOpeningBottom | DeductionOpeningLeft = DeductionOpeningRight = DeductionOpeningTop | ash T_Laserschutz | AllplanAttributes (SMT), Positionsnummer_Text
SMT | H2 Ebene +3 | 2.41 | 1.01 | TI-1F-UZ-D | Metallbau-, Schlosserarbeiten | E03 | Türmakro | 30 | - | 100 | no | UZ | OTS | 0 | ja | 11.25 | 0.000000 | E03-013-001-30 | LF | L | - | ST | PZ | DK | 0 | ST | BS | Door | 1266Rau0000012908 | 1263Mak0812768182 | 150 | NEW | EI2 30 | yes | no
SMT | H2 Ebene +2 | 2.41 | 1.01 |  | Metallbau-, Schlosserarbeiten | E02 | Makro Laufwerkskasten |  |  |  |  |  |  |  |  | 7.5 |  |  |  |  |  |  |  |  |  |  |  |  |  | 1213Mak0813407559 | 150 |  |  |  |  | 2.2 | SmartPartCompressed | 1.0
SMT | H2 Ebene +2 | 2.41 | 1.6825 | TI-2F-AG-D-O | Zimmer- und Holzbauarbeiten | E02 | Türmakro, -SmartPart | 123 | - | 100 | no | BZ | OTS | 0 | ja | 7.5 | 0.000000 | E02-F10-001-123 | - | L | - | S | PZ(v) | KD | 1 | - | BS | Door | 1215Rau0000006932 | 1213Mak0813460676 | 150 | NEW | EI2 30 | yes | no | 3.1 | SmartPartCompressed | 7.21 | Stahl-Glas-Tür | - | N | - | FWS | EMF | - | SB | A | - | S | E | E, H | (B), E, H | Typ | 0 | 3.1 | TGR-Makro | PlanNo. | TGR 1.5 | MainObject | SmartPartCompressed | 8.8375 | 1.5 | 2 | 1215Rau0000006905 | 1213Mak0813218209 | St | 2.60562 | 200 | 100 | AllplanAttributes (SMT) - Codetext: Codetext; Funktion: Flurtür; Tragendes Bauteil: yes; Typ: 0; Brennbares Material: no; Brandverhalten: 0; Brandabschnittsdefinierendes Bauteil: no; Brandschutzklasse: A; AllplanAttributes (TGR 1.5) - Ortscode_Geschoßbezeichnung: E02; OKFF: 7.5; Pset_DoorCommon - AcousticRating: 0; Reference: Codetext
SMT | H2 Ebene +2 | 2.41 | 1.9825 | TI-2F-AG-D-O | Zimmer- und Holzbauarbeiten | E02 | Türmakro, -SmartPart | 164 | X | 100 | no | BZ | - | 0 | ja | 7.5 | 0.000000 | E02-F03-001-164 | - | L | - | S | PZ(v) | KD | 1 | - |  | Door | 1215Rau0000006896 | 1213Mak0813497996 | 150 | NEW | EI2 30 | yes | no | 3.1 | SmartPartCompressed | 7.21 | Stahl-Glas-Tür | - | N |  | FWS | - | ZK | SB | A | M1 | S | E | B, C, E, H | E, G, H | Typ | 0 | 3.1 | TGR-Makro | PlanNo. | TGR 1.5 | MainObject | SmartPartCompressed | 9.1375 | 1.5 | 2 | 1215Rau0000006941 | 1213Mak0813414004 | St | 3.35763 | 200 | 100 | - | AllplanAttributes (SMT) - Codetext: Codetext; Funktion: Flurtür; Tragendes Bauteil: yes; Typ: 0; Brennbares Material: no; Brandverhalten: 0; Brandabschnittsdefinierendes Bauteil: no; Brandschutzklasse: A; ash T_E_Öffner: TÖ + FTÖ; AllplanAttributes (TGR 1.5) - Ortscode_Geschoßbezeichnung: E02; OKFF: 7.5; Pset_DoorCommon - AcousticRating: 0; Reference: Codetext
SMT | H2 Ebene +2 | 2.41 | 1.6825 | TI-2F-AG-D-O | Zimmer- und Holzbauarbeiten | E02 | Türmakro, -SmartPart | 51 | - | 100 | no | BZ | OTS | 0 | ja | 7.5 | 0.000000 | E02-F05-001-51 | - | L | - | S | PZ(v) | KD | 1 | - | BS | Door | 1215Rau0000006929 | 1213Mak0813458884 | 150 | NEW | EI2 30 | yes | no | 3.1 | SmartPartCompressed | 7.21 | Stahl-Glas-Tür | - | N | - | FWS | EMF | - | SB | A | - | S | E | E, H | (B), E, H | Typ | 0 | 3.1 | TGR-Makro | PlanNo. | TGR 1.5 | MainObject | SmartPartCompressed | 8.8375 | 1.5 | 2 | 1215Rau0000006905 | 1213Mak0813221463 | St | 2.60562 | 200 | 100 | AllplanAttributes (SMT) - Codetext: Codetext; Funktion: Flurtür; Tragendes Bauteil: yes; Typ: 0; Brennbares Material: no; Brandverhalten: 0; Brandabschnittsdefinierendes Bauteil: no; Brandschutzklasse: A; AllplanAttributes (TGR 1.5) - Ortscode_Geschoßbezeichnung: E02; OKFF: 7.5; Pset_DoorCommon - AcousticRating: 0; Reference: Codetext
SMT | H2 Ebene +2 | 2.41 | 1.6825 | TI-2F-AG-D-O | Metallbau-, Schlosserarbeiten | E02 | Türmakro | 134 | - | 100 | no | BZ | OTS | 0 | ja | 7.5 | 0.000000 | E02-F10-002-134 | - | L | - | S | PZ(v) | KD | 1 | - | BS | Door | 1215Rau0000006932 | 1213Mak0813462523 | 150 | NEW | EI2 30 | yes | no | 3.1 | SmartPartCompressed | 7.21 | Stahl-Glas-Tür | - | N | - | FWS | EMF | - | SB | A | - | S | E | E, H | (B), E, H | Typ | 0 | 3.1 | TGR-Makro | PlanNo. | TGR 1.5 | MainObject | SmartPartCompressed | 8.8375 | 1.5 | 2 | 1215Rau0000006905 | 1213Mak0813217944 | St | 2.70562 | 200 | 100 | - | AllplanAttributes (TGR 1.5) - Ortscode_Geschoßbezeichnung: E02; OKFF: 7.5; AllplanAttributes (SMT) - ash D_Detailverweis: D9; ash D_Plannummer: 1684; Pset_DoorCommon - SecurityRating: SA
SMT | H2 Ebene +1 | 2.41 | 1.01 |  | Metallbau-, Schlosserarbeiten |  | Makro Laufwerkskasten |  |  |  |  |  |  |  |  | 3.75 |  |  |  |  |  |  |  |  |  |  |  |  |  | 1163Mak0814291415 |  |  |  |  |  | 2.2 | SmartPartCompressed | 1.0 |  |  |  |  |  |  |  |  |  |  |  |  |  |  |  |  |  |  |  |  |  |  |  |  |  |  |  |  |  |  |  |  | U100
SMT | H2 Ebene +1 | 2.41 | 1.01 |  | Metallbau-, Schlosserarbeiten |  | Makro Laufwerkskasten |  |  |  |  |  |  |  |  | 3.75 |  |  |  |  |  |  |  |  |  |  |  |  |  | 1163Mak0814291427 |  |  |  |  |  | 2.2 | SmartPartCompressed | 1.0 |  |  |  |  |  |  |  |  |  |  |  |  |  |  |  |  |  |  |  |  |  |  |  |  |  |  |  |  |  |  |  |  | U100
SMT | H2 Ebene +1 | 2.41 | 1.6825 | TI-2F-AG-D-O | Zimmer- und Holzbauarbeiten | E01 | Türmakro, -SmartPart | 51 | - | 100 | no | BZ | OTS | 0 | ja | 3.75 | 0.000000 | E01-F06-001-51 | - | L | - | S | PZ(v) | KD | 1 | - | BS | Door | 1165Rau0000004677 | 1163Mak0812442701 | 150 | NEW | EI2 30 | yes | no | 3.1 | SmartPartCompressed | 7.21 | Stahl-Glas-Tür | - | N | - | FWS | EMF | - | SB | A | - | S | E | E, H | (B), E, H | Typ | 0 | 3.1 | TGR-Makro | PlanNo. | TGR 1.5 | MainObject | SmartPartCompressed | 8.8375 | 1.5 | 2 | 1165Rau0000067051 | 1163Mak0814387005 | St | 2.60562 | 200 | 100 | - | U100 | AllplanAttributes (SMT) - Codetext: Codetext; Funktion: Flurtür; Tragendes Bauteil: yes; Typ: 0; Brennbares Material: no; Brandverhalten: 0; Brandabschnittsdefinierendes Bauteil: no; Brandschutzklasse: A; Pset_DoorCommon - AcousticRating: 0; Reference: Codetext; SecurityRating: SA; AllplanAttributes (TGR 1.5) - Positionsnummer_Text: U100
SMT | H2 Ebene +1 | 2.41 | 1.6825 | TI-2F-AG-D-O | Metallbau-, Schlosserarbeiten | E01 | Türmakro | 134 | - | 100 | no | UZ | OTS | 0 | ja | 3.75 | 0.000000 | E01-F10-002-134 | - | L | - | S | PZ(v) | KD | 1 | ST | BS | Door | 1165Rau0000004725 | 1163Mak0814389237 | 150 | NEW | EI2 30 | yes | no | 3.1 | SmartPartCompressed | 7.21 | Stahl-Glas-Tür | - | N | - | FWS | EMF | - | SB | A | - | - | E | E, H | (B), E, H | Typ | 0 | 3.1 | TGR-Makro | PlanNo. | TGR 1.5 | MainObject | SmartPartCompressed | 8.8375 | 1.5 | 2 | 1165Rau0000004701 | 1163Mak0814145299 | St | 2.70562 | 200 | 100 | - | U100 | AllplanAttributes (SMT) - ash D_Detailverweis: D9; ash D_Plannummer: 1684; Pset_DoorCommon - SecurityRating: SA; AllplanAttributes (TGR 1.5) - Positionsnummer_Text: U100
SMT | H2 Ebene +1 | 2.41 | 1.6825 | TI-2F-AG-D-O | Zimmer- und Holzbauarbeiten | E01 | Türmakro, -SmartPart | 123 | - | 100 | no | UZ | OTS | 0 | ja | 3.75 | 0.000000 | E01-F11-001-123 | - | L | - | S | PZ(v) | KD | 1 | ST | BS | Door | 1165Rau0000004725 | 1163Mak0814388913 | 150 | NEW | EI2 30 | yes | no | 3.1 | SmartPartCompressed | 7.21 | Stahl-Glas-Tür | - | N | - | FWS | EMF | - | SB | A | - | - | E | E, H | (B), E, H | Typ | 0 | 3.1 | TGR-Makro | PlanNo. | TGR 1.5 | MainObject | SmartPartCompressed | 8.8375 | 1.5 | 2 | 1165Rau0000004701 | 1163Mak0814143265 | St | 2.60562 | 200 | 100 | - | U100 | AllplanAttributes (SMT) - Codetext: Codetext; Funktion: Flurtür; Tragendes Bauteil: yes; Typ: 0; Brennbares Material: no; Brandverhalten: 0; Brandabschnittsdefinierendes Bauteil: no; Brandschutzklasse: A; Pset_DoorCommon - AcousticRating: 0; Reference: Codetext; SecurityRating: SA; AllplanAttributes (TGR 1.5) - Positionsnummer_Text: U100
SMT | H2 Ebene +1 | 2.41 | 1.9825 | TI-1F-SG-D-M | Zimmer- und Holzbauarbeiten | E01 | Türmakro, -SmartPart | 164 | X | 100 | no | BZ | - | 0 | ja | 3.75 | 0.000000 | E01-F03b-001-164 | - | L | - | S | PZ(v) | KD | 1 | - |  | Door | 1165Rau0000067051 | 1163Mak0812531636 | 150 | NEW | EI2 30 | yes | no | 3.1 | SmartPartCompressed | 7.21 | Stahl-Glas-Tür | - | N | - | FWS | - | ZK | SB | A | M1 | S | E | B, C, E, H | E, G, H | Typ | 0 | 3.1 | TGR-Makro | PlanNo. | TGR 1.5 | MainObject | SmartPartCompressed | 9.1375 | 1.5 | 6 | 1166Rau0000034222 | 1163Mak0814293950 | St | 3.35763 | 200 | 100 | - | U100 | AllplanAttributes (SMT) - Codetext: Codetext; Funktion: Flurtür; Tragendes Bauteil: yes; Typ: 0; Brennbares Material: no; Brandverhalten: 0; Brandabschnittsdefinierendes Bauteil: no; Brandschutzklasse: A; ash T_E_Öffner: TÖ + FTÖ; ash T_Material Oberlicht: -; Pset_DoorCommon - AcousticRating: 0; Reference: Codetext; SecurityRating: SA; AllplanAttributes (TGR 1.5) - Positionsnummer_Text: U100
SMT | H2 Ebene 0 | 2.46 | 1.01 |  | Metallbau-, Schlosserarbeiten |  | Makro Laufwerkskasten |  |  |  |  |  |  |  |  | 0 |  |  |  |  |  |  |  |  |  |  |  |  |  | 1113Mak0813805775 |  |  |  |  |  | 2.2 | SmartPartCompressed | 1.0 |  |  |  |  |  |  |  |  |  |  |  |  |  |  |  |  |  |  |  |  |  |  |  |  |  |  |  |  |  |  |  |  | S68
SMT | H2 Ebene 0 | 2.46 | 1.01 |  | Metallbau-, Schlosserarbeiten |  | Makro Laufwerkskasten |  |  |  |  |  |  |  |  | 0 |  |  |  |  |  |  |  |  |  |  |  |  |  | 1113Mak0813805768 |  |  |  |  |  | 2.2 | SmartPartCompressed | 1.0 |  |  |  |  |  |  |  |  |  |  |  |  |  |  |  |  |  |  |  |  |  |  |  |  |  |  |  |  |  |  |  |  | S68
SMT | H2 Ebene 0 | 2.46 | 1.6825 | TI-2F-AG-D-O | Zimmer- und Holzbauarbeiten | E00 | Türmakro, -SmartPart | 51 | - | 100 | no | BZ | OTS | 0 | ja | 0 | 0.000000 | E00-F05-001-51 | - | L | - | S | PZ(v) | KD | 1 | - | BS | Door | 1115Rau0000005065 | 1113Mak0814018350 | 200 | NEW | EI2 30 | yes | yes | 3.1 | SmartPartCompressed | 7.21 | Stahl-Glas-Tür | - | N | - | FWS | EMF | - | SB | A | - | S | E | E, H | E, H | Typ | 0 | 3.1 | TGR-Makro | PlanNo. | TGR 1.5 | MainObject | SmartPartCompressed | 8.9375 | 1.5 | 2 | 1115Rau0000005053 | 1113Mak0813533192 | St | 2.60562 | 200 | 100 | - | S68 | AllplanAttributes (SMT) - Codetext: Codetext; Funktion: Flurtür; Tragendes Bauteil: yes; Typ: 0; Brennbares Material: no; Brandverhalten: 0; Brandabschnittsdefinierendes Bauteil: no; Brandschutzklasse: A; Text3: Handauslösetaster vorrichten; AllplanAttributes (TGR 1.5) - OKFF: 0; Positionsnummer_Text: S68; Pset_DoorCommon - AcousticRating: 0; Reference: Codetext; SecurityRating: SA
SMT | H2 Ebene 0 | 2.46 | 1.6825 | TI-2F-AG-D-O | Zimmer- und Holzbauarbeiten | E00 | Türmakro, -SmartPart | 123 | - | 100 | no | BZ | OTS | 0 | ja | 0 | 0.000000 | E00-F10-001-123 | - | L | - | S | PZ(v) | KD | 1 | - | BS | Door | 1115Rau0000005223 | 1113Mak0814018606 | 200 | NEW | EI2 30 | yes | yes | 3.1 | SmartPartCompressed | 7.21 | Stahl-Glas-Tür | - | N | - | FWS | EMF | - | SB | A | - | S | E | E, H | E, H | Typ | 0 | 3.1 | TGR-Makro | PlanNo. | TGR 1.5 | MainObject | SmartPartCompressed | 8.9375 | 1.5 | 2 | 1115Rau0000005053 | 1113Mak0813520831 | St | 2.60562 | 200 | 100 | - | S68 | AllplanAttributes (SMT) - Codetext: Codetext; Funktion: Flurtür; Tragendes Bauteil: yes; Typ: 0; Brennbares Material: no; Brandverhalten: 0; Brandabschnittsdefinierendes Bauteil: no; Brandschutzklasse: A; Text3: Handauslösetaster vorrichten; AllplanAttributes (TGR 1.5) - OKFF: 0; Positionsnummer_Text: S68; Pset_DoorCommon - AcousticRating: 0; Reference: Codetext; SecurityRating: SA
SMT | H2 Ebene 0 | 2.46 | 1.6825 | TI-2F-AG-D-O | Metallbau-, Schlosserarbeiten | E00 | Türmakro | 134 | - | 100 | no | BZ | OTS | 0 | ja | 0 | 0.000000 | E00-F10-002-134 | - | L | - | S | PZ(v) | KD | 1 | - | BS | Door | 1115Rau0000005072 | 1113Mak0814018894 | 200 | NEW | EI2 30 | yes | yes | 3.1 | SmartPartCompressed | 7.21 | Stahl-Glas-Tür | - | N | - | FWS | EMF | - | SB | A | - | S | E | E, H | E, H | Typ | 0 | 3.1 | TGR-Makro | PlanNo. | TGR 1.5 | MainObject | SmartPartCompressed | 8.9375 | 1.5 | 2 | 1115Rau0000005053 | 1113Mak0813537549 | St | 2.70562 | 200 | 100 | - | S68 | AllplanAttributes (TGR 1.5) - OKFF: 0; Positionsnummer_Text: S68; AllplanAttributes (SMT) - ash D_Detailverweis: D9; ash D_Plannummer: 1684; Text3: Handauslösetaster vorrichten; Pset_DoorCommon - SecurityRating: SA
SMT | H2 Ebene 0 | 2.46 | 1.9825 | TI-1F-SG-D-M | Zimmer- und Holzbauarbeiten | E00 | Türmakro, -SmartPart | 164 | X | 100 | no | BZ | - | 0 | ja | 0 | 0.000000 | E00-F03-001-164 | - | L | - | S | PZ(v) | KD | 1 | - | BGS | Door | 1115Rau0000005189 | 1113Mak0814281662 | 200 | NEW | EI2 30 | yes | yes | 3.1 | SmartPartCompressed | 7.21 | Stahl-Glas-Tür | - | N | - | FWS | - | ZK | SB | A | M1 | S | E | B, C, E | E, G | Typ | 0 | 3.1 | TGR-Makro | PlanNo. | TGR 1.5 | MainObject | SmartPartCompressed | 9.2375 | 1.5 | 2 | 1116Rau0000066600 | 1113Mak0814281649 | St | 3.35763 | 200 | 100 | - | S68 | AllplanAttributes (SMT) - Codetext: Codetext; Funktion: Flurtür; Tragendes Bauteil: yes; Typ: 0; Brennbares Material: no; Brandverhalten: 0; Brandabschnittsdefinierendes Bauteil: no; Brandschutzklasse: A; ash T_E_Öffner: TÖ + FTÖ; Text3: Schlüsselschalter neben Tür; AllplanAttributes (TGR 1.5) - OKFF: 0; Positionsnummer_Text: S68; Text4: Stahl-Glas-Tür; Pset_DoorCommon - AcousticRating: 0; Reference: Codetext; SecurityRating: SA

# IfcDoor: TGR 1.5
In: H2 Ebene 0
Type - PredefinedType: DOOR; ParameterTakesPrecedence: no
OverallHeight: 2.7 m; OverallWidth: 1.32502 m
AllplanAttributes (SMT) - Gewerk: Zimmer- und Holzbauarbeiten; V6: 0 m; V7: 0 m; V8: 0 m; V9: 0; Ortscode_Geschoßbezeichnung: E00; Programmversion: 3.1; Text1: 158; Text4: Stahl-Glas-Tür; Bezeichnung: SMT; Material: TI-1F-AG-D; Plugin_Bezeichnung: MainObject; Plugin_Objektname: SmartPartCompressed; Glasanteil_berücksichtigen: 100; Version: 7.21; ash T_Sichtschutz: -; ash R_Verweis Wandansicht: -; ash T_Zulage Schachttür: no; ash T_Dichtschließend: no; ash T_Panik: -; ash T_Zarge_Typ: BZ; ash T_Türschließer: OTS; ash T_Gewerk Los: -; ash T_Erforderl. Durchgangsbreite: 0 m; ash T_Türblatt sichtbar 2D: ja; ash T_Zusatzfunktion Panikschloss: -; ash T_Fluchtwegsicherung: -; ash T_Standflügel-Betätigung: -; ash T_Zusatzfunktion Türschließer: -; ash T_Türschließer-Montage: -; ash T_Feststellanlage (FSA): EMF; ash T_Zusätzliche Rauchmelder: -; ash T_Zusätzl. Anschluss an BMA: -; ash T_Impulsgeber: -; ash T_Sicherheits-Sensorleisten: -; ash T_Anschl. an Zuttrittskontrolle: -; ash T_Anschl. an Einbruchmeld.anl.: -; ash T_Klemmschutz: -; ash T_LV-Positions-Nr.: -; ash T_Plan-Nr.: -; ash T_Sonstiges, Bemerkungen: -; OKFF: 0; ash T_Bodentürstopper: -; ash T_nicht abschließbar: no; ash T_Material Seitenteil: -; ash T_Strahlenschutz: 0.000000; ash T_Tür-Nr.: E00-063-001-158; ash T_Kantengeometrie: -; ash T_Kantenmaterial: -; ash T_Blatt_Oberfläche: L; ash T_Erford. Durgangshöhe: 0 m; ash T_Laserschutz: -; ash T_Rammschutz: -; ash T_Fluchtwegrichtung: -; ash T_Anschlag Gangflügel: -; ash T_Bodendichtung: Ja; ash T_Lüftungsgitter: 0 m2; ash T_Feuchtebeständigkeit: -; ash T_Automatik_Antrieb: -; ash T_Sturz: S; ash T_Blatt_Material: S; ash T_Schlossfunktion: E; ash T_Schliesszylinder: PZ; ash T_Beschlag: DD; ash T_Glasausschnitt: -; ash T_Sonder_Wandmaterial: -; ash T_Anz_Reedkontakte: 0; ash T_Anz_Riegelkontakte: 1; ash T_Schallschutz: -; ash T_Zarge_Material: -; ash T_Bodeneinstand: -; ash T_Raum zugehörigkeit: BS; ash T_Blatt_Farbe: -; ash D_Detailverweis: D4; ash D_Plannummer: 1684; ash T_Steuerung (BS): E; Positionsnummer_Text: S68; Attributset-Objekt: Door; P_ID: 1116Rau0000066600; Allright_Bauteil_ID: 1113Mak0813370641; Abrechnungsart: St; Objektname: Türmakro, -SmartPart
AllplanAttributes (TGR 1.5) - Codetext: Typ; V6: 0 m; V7: 0 m; V8: 0 m; V9: 0; Programmversion: 3.1; Objektname: TGR-Makro; Text1: PlanNo.; Bezeichnung: TGR 1.5; Plugin_Bezeichnung: MainObject; Plugin_Objektname: SmartPartCompressed; Gesamtlänge: 8.58002; Version: 1.5; OKFF: 0; ash T_Türprofilnummer: 6; Positionsnummer_Text: S68; P_ID: 1116Rau0000066600; Allright_Bauteil_ID: 1113Mak0813447515; Abrechnungsart: St
AllplanQuantities - GlassSurface: 2.03978; HeightWindowSillOutside: 0; HeightWindowSillInside: 0; OffsetOpeningBottom: 200; OffsetOpeningTop: 0; OffsetOpeningLeft: 0; OffsetOpeningRight: 0; DeductionOpeningBottom: 100; DeductionOpeningLeft: 0; DeductionOpeningRight: 0; DeductionOpeningTop: 0
Pset_DoorCommon - Status: NEW; IsExternal: no; FireRating: EI2 60; ThermalTransmittance: 0 W/K/m2; HandicapAccessible: no; SmokeStop: yes; SelfClosing: yes; FireExit: no; SecurityRating: SA

# IfcDoor: TGR 1.6 (16)
In: H2 Ebene +3
Type - PredefinedType: DOOR; ParameterTakesPrecedence: no
AllplanAttributes (SMT) - V6: 0 m; V7: 0 m; V8: 0 m; V9: 0; Ortscode_Geschoßbezeichnung: E03; Text2: -; Bezeichnung: SMT; Plugin_Bezeichnung: MainObject; Plugin_Objektname: SmartPartCompressed; Glasanteil_berücksichtigen: 100; ash T_Zarge_Typ: UZ; ash T_Erforderl. Durchgangsbreite: 0 m; ash T_Türblatt sichtbar 2D: ja; OKFF: 11.25; ash T_Strahlenschutz: 0.000000; ash T_Erford. Durgangshöhe: 0 m; ash T_Anschlag Gangflügel: -; ash T_Lüftungsgitter: 0 m2; ash T_Anz_Reedkontakte: 0; ash T_Zarge_Material: ST
AllplanAttributes (TGR 1.6) - Codetext: Typ; V6: 0 m; V7: 0 m; V8: 0 m; V9: 0; Programmversion: 3.1; Objektname: TGR-Makro; Text1: PlanNo.; Bezeichnung: TGR 1.6; Plugin_Bezeichnung: MainObject; Plugin_Objektname: SmartPartCompressed; Version: 1.6; OKFF: 11.25; Abrechnungsart: St
AllplanQuantities - GlassSurface: 0; HeightWindowSillOutside: 0; HeightWindowSillInside: 0; OffsetOpeningBottom: 150; OffsetOpeningTop: 0; OffsetOpeningLeft: 0; OffsetOpeningRight: 0; DeductionOpeningBottom: 100; DeductionOpeningLeft: 40; DeductionOpeningRight: 40; DeductionOpeningTop: 40
Pset_DoorCommon - Status: NEW; IsExternal: no; ThermalTransmittance: 0 W/K/m2; HandicapAccessible: no; FireExit: no
Name | OverallHeight (m) | OverallWidth (m) | Gewerk | Programmversion | Objektname | Text1 | Material | Version | ash T_Zulage Schachttür = ash T_nicht abschließbar | ash T_Dichtschließend | ash T_Türschließer | ash T_Tür-Nr. | ash T_Kantengeometrie | ash T_Blatt_Oberfläche | ash T_Blatt_Material | ash T_Schliesszylinder | ash T_Beschlag | ash T_Anz_Riegelkontakte | ash T_Schallschutz | ash T_Raum zugehörigkeit | Attributset-Objekt | P_ID | AllplanAttributes (SMT), Allright_Bauteil_ID | Abrechnungsart | Gesamtlänge | ash T_Türprofilnummer | AllplanAttributes (TGR 1.6), Allright_Bauteil_ID | FireRating | SmokeStop = SelfClosing | ash T_Feststellanlage (FSA)
TGR 1.6 | 2.41 | 1.01 | Metallbau-, Schlosserarbeiten | 3.1 | Türmakro | 3 | TI-1F-UZ-D | 7.21 | no | no | OTS | E03-002-001-3 | LF | L | ST | PZ | KD | 0 | - | BGS | Door | 1265Rau0000000034 | 1263Mak0812547702 | St | 7.86 | 5 | 1263Mak0812947376 | EI2 30 | yes
TGR 1.6 | 2.41 | 1.01 | Trockenbauarbeiten | 3.1 | Wand | 9 | TI-1F-UZ-D | 7.21 | no | no | OTS | E03-005-001-9 | LF | L | ST | PZ | KD | 0 | - | BGS | Door | 1265Rau0000000034 | 1263Mak0812547700 | m² | 7.86 | 5 | 1263Mak0812947324 | EI2 30 | yes | - | AllplanAttributes (SMT) - 2D Interaktion: yes; Codetext: Codetext; Tragendes Bauteil: no; Typ: 0; Brennbares Material: no; Brandverhalten: 0; Brandabschnittsdefinierendes Bauteil: no; Brandschutzklasse: A; W_Deckenanschluss: Gleitender Deckenanschluss Fall 01; Pset_DoorCommon - AcousticRating: 0; Reference: Codetext
TGR 1.6 | 2.41 | 1.26 | Metallbau-, Schlosserarbeiten | 3.0 | Türmakro | 8 | TI-1F-UZ-D | 8.11 | no | no | OTS | E03-004-001-8 | LF | L | ST | PZ | KD | 0 | - | BGS | Door | 1265Rau0000000034 | 1263Mak0812768054 | St | 8.11 | 3 | 1263Mak0812947341 | EI2 30 | yes | - | AllplanAttributes (SMT) - Codetext: Codetext; Tragendes Bauteil: yes; Typ: 0; Brennbares Material: no; Brandverhalten: 0; Brandabschnittsdefinierendes Bauteil: no; Brandschutzklasse: A; Pset_DoorCommon - AcousticRating: 0; Reference: Codetext
TGR 1.6 | 2.41 | 1.01 | Metallbau-, Schlosserarbeiten | 3.0 | Türmakro | 14 | TI-1F-UZ-D-KZ-B | 8.11 | no | no | OTS | E03-017-001-14 | LF | L | ST | PZ | KD | 0 | - | BGS | Door | 1265Rau0000000034 | 1263Mak0812547706 | St | 7.86 | 5 | 1263Mak0812947274 | EI2 30 | yes | - | AllplanAttributes (SMT) - Codetext: Codetext; Tragendes Bauteil: yes; Typ: 0; Brennbares Material: no; Brandverhalten: 0; Brandabschnittsdefinierendes Bauteil: no; Brandschutzklasse: A; Pset_DoorCommon - AcousticRating: 0; Reference: Codetext
TGR 1.6 | 2.41 | 1.01 | Metallbau-, Schlosserarbeiten | 3.0 | Türmakro | 13 | TI-1F-UZ-D | 8.11 | no | no | OTS | E03-007-001-13 | LF | L | ST | PZ | KD | 0 | - | BGS | Door | 1265Rau0000000034 | 1263Mak0812547703 | St | 7.86 | 5 | 1263Mak0812947289 | EI2 30 | yes | - | AllplanAttributes (SMT) - Codetext: Codetext; Tragendes Bauteil: yes; Typ: 0; Brennbares Material: no; Brandverhalten: 0; Brandabschnittsdefinierendes Bauteil: no; Brandschutzklasse: A; Pset_DoorCommon - AcousticRating: 0; Reference: Codetext
TGR 1.6 | 2.5 | 0.885 | Metallbau-, Schlosserarbeiten | 3.0 | Türmakro | 29 | TI-1F-UZ-D-N | 8.11 |  |  |  | E03-012a-001-29 | 2F | HPL | HO | WC | DD | 0 | - | BS | Door | 1266Rau0000015511 | 1263Mak0812595902 | St | 7.685 | 5 | 1263Mak0812947244 | AllplanAttributes (SMT) - ash T_Unterschnitt: -; ash T_Kantenmaterial: PU; ash T_Feuchtebeständigkeit: N
TGR 1.6 | 2.41 | 1.01 | Metallbau-, Schlosserarbeiten | 3.1 | Türmakro | 37 | TI-1F-UZ-D-KZ-B | 7.21 | no | no | OTS | E03-017-001-37 | LF | L | ST | PZ | DK | 0 | - | BS | Door | 1266Rau0000012932 | 1263Mak0812768304 | St | 7.86 | 5 | 1263Mak0812947447 | EI2 30 | yes | -
TGR 1.6 | 2.41 | 1.01 | Metallbau-, Schlosserarbeiten | 3.1 | Türmakro | 39 | TI-1F-UZ-D | 7.21 | no | no | OTS | E03-018-002-39 | LF | L | ST | PZ | DK | 0 | - | BGS | Door | 1265Rau0000000012 | 1263Mak0812976535 | St | 7.86 | 5 | 1263Mak0812976484 | EI2 30 | yes | -
TGR 1.6 | 2.41 | 1.01 | Metallbau-, Schlosserarbeiten | 3.1 | Türmakro | 40 | TI-1F-UZ-D | 7.21 | no | no | OTS | E03-015-001-40 | LF | L | ST | PZ | KD | 0 | - | BS | Door | 1265Rau0000000012 | 1263Mak0812547699 | St | 7.86 | 5 | 1263Mak0812947421 | EI2 30 | yes | -
TGR 1.6 | 2.41 | 1.01 | Metallbau-, Schlosserarbeiten | 3.1 | Türmakro | 43 | TI-1F-UZ-D | 7.21 | no | no | OTS | E03-019-001-43 | LF | L | ST | PZ | KD | 0 | - | BGS | Door | 1265Rau0000000012 | 1263Mak0812767682 | St | 7.86 | 5 | 1263Mak0812947468 | EI2 30 | yes | -
TGR 1.6 | 2.16 | 1.01 | Metallbau-, Schlosserarbeiten | 3.1 | Türmakro | 18 | TI-1F-UZ-D-N | 7.21 |  |  |  | E03-009a-001-18 | 2F | HPL | HO | WC | DD | 0 | 27 dB | BS | Door | 1266Rau0812598643 | 1263Mak0812593398 | St | 7.81 | 5 | 1263Mak0812947400 | AllplanAttributes (SMT) - ash T_Unterschnitt: -; ash T_Kantenmaterial: PU; ash T_Feuchtebeständigkeit: N
TGR 1.6 | 2.41 | 1.01 |  | 3.1 | Türmakro, -SmartPart | 21 | TI-1F-UZ-ZK | 7.21 | no | yes |  | E03-009-001-21 | 2F | HPL | HO | WC | DK | 1 | 27 dB | BS |  | 1266Rau0812598643 | 1263Mak0812843162 | St | 7.86 | 5 | 1263Mak0812947382 | - | no | - | AllplanAttributes (SMT) - ash T_Unterschnitt: -; ash T_Kantenmaterial: PU; ash T_Feuchtebeständigkeit: F; ash T_Steuerung (BG): E
TGR 1.6 | 2.41 | 1.01 |  | 3.1 | Türmakro, -SmartPart | 17 | TI-1F-UZ-ZK | 7.21 | no | yes |  | E03-009-002-17 | 2F | HPL | HO | WC | DK | 1 | 27 dB | BS | Door | 1266Rau0812598643 | 1263Mak0812975327 | St | 7.86 | 5 | 1263Mak0812975242 | - | no | - | AllplanAttributes (SMT) - ash T_Unterschnitt: -; ash T_Kantenmaterial: PU; ash T_Feuchtebeständigkeit: F; ash T_Steuerung (BG): E
TGR 1.6 | 2.16 | 0.76 | Metallbau-, Schlosserarbeiten | 3.1 | Türmakro | 22 | TI-1F-UZ-D-N | 7.21 |  |  |  | E03-010a-001-22 | 2F | HPL | HO | WC | DD | 0 | 27 dB | BS | Door | 1266Rau0000015290 | 1263Mak0812839291 | St | 7.56 | 5 | 1263Mak0812947418 | AllplanAttributes (SMT) - ash T_Unterschnitt: -; ash T_Kantenmaterial: PU; ash T_Feuchtebeständigkeit: N
TGR 1.6 | 2.16 | 0.76 | Metallbau-, Schlosserarbeiten | 3.1 | Türmakro | 23 | TI-1F-UZ-D-N | 7.21 |  | no | OTS | E03-010b-001-23 | 2F | HPL | HO | WC | DD | 0 | 27 dB | BS | Door | 1266Rau0000012955 | 1263Mak0812772366 | St | 7.56 | 5 | 1263Mak0812947415 | EI2 30 | yes | AllplanAttributes (SMT) - ash T_Unterschnitt: -; ash T_Kantenmaterial: PU; ash T_Feuchtebeständigkeit: N
TGR 1.6 | 2.5 | 1.01 | Metallbau-, Schlosserarbeiten | 3.0 | Türmakro | 16 | TI-1F-UZ-D | 8.11 | no | no | OTS | E03-008-001-16 | LF | L | ST | PZ | DK | 0 | - | BS | Door | 1266Rau0000015419 | 1263Mak0812546146 | St | 7.86 | 5 | 1263Mak0812947321 | EI2 30 | yes | -

# IfcElementAssembly (227)
Name | In | Allright_Bauteil_ID | Abrechnungsart | Objektname
 | Modellreferenzen | 5997Ach0000001398 | m³ | Achsraster
 | Modellreferenzen | 5997Ach0000001647 | m³ | Achsraster
 | Modellreferenzen | 5997Ach0000001902 | m³ | Achsraster
 | H2 Ebene +4/ Dachebene | 1408Elg0000000664 | St | Elementgruppe
 | H2 Ebene +4/ Dachebene | 1408Elg0000000658 | St | Elementgruppe
 | H2 Ebene +4/ Dachebene | 1408Elg0000000676 | St | Elementgruppe
 | H2 Ebene +4/ Dachebene | 1408Elg0000000677 | St | Elementgruppe
Geländer+Abstand | H2 Ebene +2 | 1213Elg0813561768 | St | Elementgruppe
Geländer+Abstand | H2 Ebene +2 | 1213Elg0813561773 | St | Elementgruppe
Geländer+Abstand | H2 Ebene +2 | 1213Elg0813561779 | St | Elementgruppe
Geländer+Abstand | H2 Ebene +2 | 1213Elg0813561791 | St | Elementgruppe
Geländer+Abstand | H2 Ebene +2 | 1213Elg0813561797 | St | Elementgruppe
Geländer+Abstand | H2 Ebene +2 | 1213Elg0813561821 | St | Elementgruppe
Geländer+Abstand | H2 Ebene +2 | 1213Elg0813561827 | St | Elementgruppe
Geländer+Abstand | H2 Ebene +2 | 1213Elg0813561833 | St | Elementgruppe
Geländer+Abstand | H2 Ebene +2 | 1213Elg0813561839 | St | Elementgruppe
Geländer+Abstand | H2 Ebene +2 | 1213Elg0813561845 | St | Elementgruppe
Geländer+Abstand | H2 Ebene +2 | 1213Elg0813561851 | St | Elementgruppe
Geländer+Abstand | H2 Ebene +2 | 1213Elg0813561857 | St | Elementgruppe
Geländer+Abstand | H2 Ebene +2 | 1213Elg0813561875 | St | Elementgruppe
Geländer+Abstand | H2 Ebene +2 | 1213Elg0813561881 | St | Elementgruppe
Geländer+Abstand | H2 Ebene +2 | 1213Elg0813561887 | St | Elementgruppe
Geländer+Abstand | H2 Ebene +2 | 1213Elg0813561917 | St | Elementgruppe
Geländer+Abstand | H2 Ebene +2 | 1213Elg0813561923 | St | Elementgruppe
Geländer+Abstand | H2 Ebene +2 | 1213Elg0813561929 | St | Elementgruppe
Geländer+Abstand | H2 Ebene +2 | 1213Elg0813561953 | St | Elementgruppe
Geländer+Abstand | H2 Ebene +2 | 1213Elg0813561959 | St | Elementgruppe
Geländer+Abstand | H2 Ebene +2 | 1213Elg0813561971 | St | Elementgruppe
Geländer+Abstand | H2 Ebene +2 | 1213Elg0813561977 | St | Elementgruppe
Geländer+Abstand | H2 Ebene +2 | 1213Elg0813561989 | St | Elementgruppe
Geländer+Abstand | H2 Ebene +2 | 1213Elg0813561995 | St | Elementgruppe
Geländer+Abstand | H2 Ebene +2 | 1213Elg0813562001 | St | Elementgruppe
Geländer+Abstand | H2 Ebene +2 | 1213Elg0813562013 | St | Elementgruppe
Geländer+Abstand | H2 Ebene +2 | 1213Elg0813562025 | St | Elementgruppe
Geländer+Abstand | H2 Ebene +2 | 1213Elg0813562031 | St | Elementgruppe
Geländer+Abstand | H2 Ebene +2 | 1213Elg0813562037 | St | Elementgruppe
Geländer+Abstand | H2 Ebene +2 | 1213Elg0813562049 | St | Elementgruppe
Geländer+Abstand | H2 Ebene +2 | 1213Elg0813562061 | St | Elementgruppe
Geländer+Abstand | H2 Ebene +2 | 1213Elg0813562067 | St | Elementgruppe
Geländer+Abstand | H2 Ebene +2 | 1213Elg0813562073 | St | Elementgruppe
Geländer+Abstand | H2 Ebene +2 | 1213Elg0813562079 | St | Elementgruppe
Geländer+Abstand | H2 Ebene +2 | 1213Elg0813562097 | St | Elementgruppe
Geländer+Abstand | H2 Ebene +2 | 1213Elg0813562121 | St | Elementgruppe
Geländer+Abstand | H2 Ebene +2 | 1213Elg0813562127 | St | Elementgruppe
Geländer+Abstand | H2 Ebene +2 | 1213Elg0813562133 | St | Elementgruppe
Geländer+Abstand | H2 Ebene +2 | 1213Elg0813562151 | St | Elementgruppe
Geländer+Abstand | H2 Ebene +2 | 1213Elg0813562169 | St | Elementgruppe
Geländer+Abstand | H2 Ebene +2 | 1213Elg0813562175 | St | Elementgruppe
Geländer+Abstand | H2 Ebene +2 | 1213Elg0813562181 | St | Elementgruppe
Geländer+Abstand | H2 Ebene +2 | 1213Elg0813562187 | St | Elementgruppe
Geländer+Abstand | H2 Ebene +2 | 1213Elg0813562193 | St | Elementgruppe
Geländer+Abstand | H2 Ebene +2 | 1213Elg0813562199 | St | Elementgruppe
Geländer+Abstand | H2 Ebene +2 | 1213Elg0813562205 | St | Elementgruppe
Geländer+Abstand | H2 Ebene +2 | 1213Elg0813562211 | St | Elementgruppe
Geländer+Abstand | H2 Ebene +2 | 1213Elg0813562247 | St | Elementgruppe
Geländer+Abstand | H2 Ebene +2 | 1213Elg0813562253 | St | Elementgruppe
Geländer+Abstand | H2 Ebene +2 | 1213Elg0813562259 | St | Elementgruppe
Geländer+Abstand | H2 Ebene +2 | 1213Elg0813562265 | St | Elementgruppe
Geländer+Abstand | H2 Ebene +2 | 1213Elg0813562271 | St | Elementgruppe
Geländer+Abstand | H2 Ebene +2 | 1213Elg0813562277 | St | Elementgruppe
Geländer+Abstand | H2 Ebene +2 | 1213Elg0813562283 | St | Elementgruppe
Geländer+Abstand | H2 Ebene +2 | 1213Elg0813562289 | St | Elementgruppe
Geländer+Abstand | H2 Ebene +2 | 1213Elg0813562295 | St | Elementgruppe
Geländer+Abstand | H2 Ebene +2 | 1213Elg0813562301 | St | Elementgruppe
Geländer+Abstand | H2 Ebene +2 | 1213Elg0813562319 | St | Elementgruppe
Geländer+Abstand | H2 Ebene +2 | 1213Elg0813562325 | St | Elementgruppe
Geländer+Abstand | H2 Ebene +2 | 1213Elg0813562331 | St | Elementgruppe
Geländer+Abstand | H2 Ebene +2 | 1213Elg0813562337 | St | Elementgruppe
Geländer+Abstand | H2 Ebene +2 | 1213Elg0813562091 | St | Elementgruppe
Geländer+Abstand | H2 Ebene +2 | 1213Elg0813562103 | St | Elementgruppe
Geländer+Abstand | H2 Ebene +2 | 1213Elg0813561869 | St | Elementgruppe
Geländer+Abstand | H2 Ebene +2 | 1213Elg0813561863 | St | Elementgruppe
Geländer+Abstand | H2 Ebene +2 | 1213Elg0813562007 | St | Elementgruppe
Geländer+Abstand | H2 Ebene +2 | 1213Elg0813562043 | St | Elementgruppe
Geländer+Abstand | H2 Ebene +2 | 1213Elg0813562055 | St | Elementgruppe
Geländer+Abstand | H2 Ebene +2 | 1213Elg0813562307 | St | Elementgruppe
Geländer+Abstand | H2 Ebene +2 | 1213Elg0813562241 | St | Elementgruppe
Geländer+Abstand | H2 Ebene +2 | 1213Elg0813562235 | St | Elementgruppe
Geländer+Abstand | H2 Ebene +2 | 1213Elg0813562139 | St | Elementgruppe
Geländer+Abstand | H2 Ebene +2 | 1213Elg0813562145 | St | Elementgruppe | AllplanAttributes - Bezeichnung: Geländer+Abstand
Geländer+Abstand | H2 Ebene +2 | 1213Elg0813561935 | St | Elementgruppe | AllplanAttributes - Bezeichnung: Geländer+Abstand; ash D_Detailverweis: D8; ash D_Plannummer: 1684
Geländer+Abstand | H2 Ebene +2 | 1213Elg0813562349 | St | Elementgruppe
Geländer+Abstand | H2 Ebene +2 | 1213Elg0813730183 | St | Elementgruppe
Geländer+Abstand | H2 Ebene +1 | 1163Elg0814482493 | St | Elementgruppe
Geländer+Abstand | H2 Ebene +1 | 1163Elg0814482498 | St | Elementgruppe
Geländer+Abstand | H2 Ebene +1 | 1163Elg0814482504 | St | Elementgruppe
Geländer+Abstand | H2 Ebene +1 | 1163Elg0814482522 | St | Elementgruppe
Geländer+Abstand | H2 Ebene +1 | 1163Elg0814482552 | St | Elementgruppe
Geländer+Abstand | H2 Ebene +1 | 1163Elg0814482558 | St | Elementgruppe
Geländer+Abstand | H2 Ebene +1 | 1163Elg0814482600 | St | Elementgruppe
Geländer+Abstand | H2 Ebene +1 | 1163Elg0814482606 | St | Elementgruppe
Geländer+Abstand | H2 Ebene +1 | 1163Elg0814482612 | St | Elementgruppe
Geländer+Abstand | H2 Ebene +1 | 1163Elg0814482648 | St | Elementgruppe
Geländer+Abstand | H2 Ebene +1 | 1163Elg0814482654 | St | Elementgruppe
Geländer+Abstand | H2 Ebene +1 | 1163Elg0814482678 | St | Elementgruppe
Geländer+Abstand | H2 Ebene +1 | 1163Elg0814482684 | St | Elementgruppe
Geländer+Abstand | H2 Ebene +1 | 1163Elg0814482696 | St | Elementgruppe
Geländer+Abstand | H2 Ebene +1 | 1163Elg0814482720 | St | Elementgruppe
Geländer+Abstand | H2 Ebene +1 | 1163Elg0814482726 | St | Elementgruppe
Geländer+Abstand | H2 Ebene +1 | 1163Elg0814482750 | St | Elementgruppe
Geländer+Abstand | H2 Ebene +1 | 1163Elg0814482756 | St | Elementgruppe
Geländer+Abstand | H2 Ebene +1 | 1163Elg0814482762 | St | Elementgruppe
Geländer+Abstand | H2 Ebene +1 | 1163Elg0814482774 | St | Elementgruppe
Geländer+Abstand | H2 Ebene +1 | 1163Elg0814482786 | St | Elementgruppe
Geländer+Abstand | H2 Ebene +1 | 1163Elg0814482792 | St | Elementgruppe
Geländer+Abstand | H2 Ebene +1 | 1163Elg0814482798 | St | Elementgruppe
Geländer+Abstand | H2 Ebene +1 | 1163Elg0814482804 | St | Elementgruppe
Geländer+Abstand | H2 Ebene +1 | 1163Elg0814482852 | St | Elementgruppe
Geländer+Abstand | H2 Ebene +1 | 1163Elg0814482858 | St | Elementgruppe
Geländer+Abstand | H2 Ebene +1 | 1163Elg0814482876 | St | Elementgruppe
Geländer+Abstand | H2 Ebene +1 | 1163Elg0814482894 | St | Elementgruppe
Geländer+Abstand | H2 Ebene +1 | 1163Elg0814482900 | St | Elementgruppe
Geländer+Abstand | H2 Ebene +1 | 1163Elg0814482906 | St | Elementgruppe
Geländer+Abstand | H2 Ebene +1 | 1163Elg0814482912 | St | Elementgruppe
Geländer+Abstand | H2 Ebene +1 | 1163Elg0814482918 | St | Elementgruppe
Geländer+Abstand | H2 Ebene +1 | 1163Elg0814482924 | St | Elementgruppe
Geländer+Abstand | H2 Ebene +1 | 1163Elg0814482930 | St | Elementgruppe
Geländer+Abstand | H2 Ebene +1 | 1163Elg0814482936 | St | Elementgruppe
Geländer+Abstand | H2 Ebene +1 | 1163Elg0814482972 | St | Elementgruppe
Geländer+Abstand | H2 Ebene +1 | 1163Elg0814482978 | St | Elementgruppe
Geländer+Abstand | H2 Ebene +1 | 1163Elg0814482984 | St | Elementgruppe
Geländer+Abstand | H2 Ebene +1 | 1163Elg0814482990 | St | Elementgruppe
Geländer+Abstand | H2 Ebene +1 | 1163Elg0814482996 | St | Elementgruppe
Geländer+Abstand | H2 Ebene +1 | 1163Elg0814483002 | St | Elementgruppe
Geländer+Abstand | H2 Ebene +1 | 1163Elg0814483008 | St | Elementgruppe
Geländer+Abstand | H2 Ebene +1 | 1163Elg0814483014 | St | Elementgruppe
Geländer+Abstand | H2 Ebene +1 | 1163Elg0814483020 | St | Elementgruppe
Geländer+Abstand | H2 Ebene +1 | 1163Elg0814483044 | St | Elementgruppe
Geländer+Abstand | H2 Ebene +1 | 1163Elg0814483050 | St | Elementgruppe
Geländer+Abstand | H2 Ebene +1 | 1163Elg0814483056 | St | Elementgruppe
Geländer+Abstand | H2 Ebene +1 | 1163Elg0814483062 | St | Elementgruppe
Geländer+Abstand | H2 Ebene +1 | 1163Elg0814482594 | St | Elementgruppe
Geländer+Abstand | H2 Ebene +1 | 1163Elg0814482588 | St | Elementgruppe
Geländer+Abstand | H2 Ebene +1 | 1163Elg0814482732 | St | Elementgruppe
Geländer+Abstand | H2 Ebene +1 | 1163Elg0814482768 | St | Elementgruppe
Geländer+Abstand | H2 Ebene +1 | 1163Elg0814482780 | St | Elementgruppe
Geländer+Abstand | H2 Ebene +1 | 1163Elg0814483032 | St | Elementgruppe
Geländer+Abstand | H2 Ebene +1 | 1163Elg0814482966 | St | Elementgruppe
Geländer+Abstand | H2 Ebene +1 | 1163Elg0814482960 | St | Elementgruppe
Geländer+Abstand | H2 Ebene +1 | 1163Elg0814482864 | St | Elementgruppe
Geländer+Abstand | H2 Ebene +1 | 1163Elg0814482516 | St | Elementgruppe
Geländer+Abstand | H2 Ebene +1 | 1163Elg0814482546 | St | Elementgruppe
Geländer+Abstand | H2 Ebene +1 | 1163Elg0814482564 | St | Elementgruppe
Geländer+Abstand | H2 Ebene +1 | 1163Elg0814482570 | St | Elementgruppe
Geländer+Abstand | H2 Ebene +1 | 1163Elg0814482576 | St | Elementgruppe
Geländer+Abstand | H2 Ebene +1 | 1163Elg0814482582 | St | Elementgruppe
Geländer+Abstand | H2 Ebene +1 | 1163Elg0814482642 | St | Handlauf | AllplanAttributes - Bezeichnung: Geländer+Abstand
Geländer+Abstand | H2 Ebene +1 | 1163Elg0814482702 | St | Handlauf
Geländer+Abstand | H2 Ebene +1 | 1163Elg0814482738 | St | Handlauf
Geländer+Abstand | H2 Ebene +1 | 1163Elg0814482822 | St | Handlauf
Geländer+Abstand | H2 Ebene +1 | 1163Elg0814483074 | St | Handlauf
Geländer+Abstand | H2 Ebene +1 | 1163Elg0814482828 | St | Handlauf
Geländer+Abstand | H2 Ebene +1 | 1163Elg0814482816 | St | Handlauf
Geländer+Abstand | H2 Ebene +1 | 1163Elg0814482660 | St | Elementgruppe | AllplanAttributes - Bezeichnung: Geländer+Abstand; ash D_Detailverweis: D8; ash D_Plannummer: 1684
Geländer+Abstand | H2 Ebene +1 | 1163Elg0814482714 | St | Handlauf
Geländer+Abstand | H2 Ebene 0 | 1113Elg0814016043 | St | Elementgruppe
Geländer+Abstand | H2 Ebene 0 | 1113Elg0814016048 | St | Elementgruppe
Geländer+Abstand | H2 Ebene 0 | 1113Elg0814016054 | St | Elementgruppe
Geländer+Abstand | H2 Ebene 0 | 1113Elg0814016066 | St | Elementgruppe
Geländer+Abstand | H2 Ebene 0 | 1113Elg0814016072 | St | Elementgruppe
Geländer+Abstand | H2 Ebene 0 | 1113Elg0814016096 | St | Elementgruppe
Geländer+Abstand | H2 Ebene 0 | 1113Elg0814016114 | St | Elementgruppe
Geländer+Abstand | H2 Ebene 0 | 1113Elg0814016120 | St | Elementgruppe
Geländer+Abstand | H2 Ebene 0 | 1113Elg0814016126 | St | Elementgruppe
Geländer+Abstand | H2 Ebene 0 | 1113Elg0814016132 | St | Elementgruppe
Geländer+Abstand | H2 Ebene 0 | 1113Elg0814016162 | St | Elementgruppe
Geländer+Abstand | H2 Ebene 0 | 1113Elg0814016198 | St | Elementgruppe
Geländer+Abstand | H2 Ebene 0 | 1113Elg0814016204 | St | Elementgruppe
Geländer+Abstand | H2 Ebene 0 | 1113Elg0814016234 | St | Elementgruppe
Geländer+Abstand | H2 Ebene 0 | 1113Elg0814016312 | St | Elementgruppe
Geländer+Abstand | H2 Ebene 0 | 1113Elg0814016324 | St | Elementgruppe
Geländer+Abstand | H2 Ebene 0 | 1113Elg0814016336 | St | Elementgruppe
Geländer+Abstand | H2 Ebene 0 | 1113Elg0814016342 | St | Elementgruppe
Geländer+Abstand | H2 Ebene 0 | 1113Elg0814016348 | St | Elementgruppe
Geländer+Abstand | H2 Ebene 0 | 1113Elg0814016354 | St | Elementgruppe
Geländer+Abstand | H2 Ebene 0 | 1113Elg0814016372 | St | Elementgruppe
Geländer+Abstand | H2 Ebene 0 | 1113Elg0814016402 | St | Elementgruppe
Geländer+Abstand | H2 Ebene 0 | 1113Elg0814016408 | St | Elementgruppe
Geländer+Abstand | H2 Ebene 0 | 1113Elg0814016444 | St | Elementgruppe
Geländer+Abstand | H2 Ebene 0 | 1113Elg0814016450 | St | Elementgruppe
Geländer+Abstand | H2 Ebene 0 | 1113Elg0814016456 | St | Elementgruppe
Geländer+Abstand | H2 Ebene 0 | 1113Elg0814016462 | St | Elementgruppe
Geländer+Abstand | H2 Ebene 0 | 1113Elg0814016468 | St | Elementgruppe
Geländer+Abstand | H2 Ebene 0 | 1113Elg0814016474 | St | Elementgruppe
Geländer+Abstand | H2 Ebene 0 | 1113Elg0814016480 | St | Elementgruppe
Geländer+Abstand | H2 Ebene 0 | 1113Elg0814016522 | St | Elementgruppe
Geländer+Abstand | H2 Ebene 0 | 1113Elg0814016528 | St | Elementgruppe
Geländer+Abstand | H2 Ebene 0 | 1113Elg0814016534 | St | Elementgruppe
Geländer+Abstand | H2 Ebene 0 | 1113Elg0814016540 | St | Elementgruppe
Geländer+Abstand | H2 Ebene 0 | 1113Elg0814016546 | St | Elementgruppe
Geländer+Abstand | H2 Ebene 0 | 1113Elg0814016552 | St | Elementgruppe
Geländer+Abstand | H2 Ebene 0 | 1113Elg0814016558 | St | Elementgruppe
Geländer+Abstand | H2 Ebene 0 | 1113Elg0814016570 | St | Elementgruppe
Geländer+Abstand | H2 Ebene 0 | 1113Elg0814016594 | St | Elementgruppe
Geländer+Abstand | H2 Ebene 0 | 1113Elg0814016600 | St | Elementgruppe
Geländer+Abstand | H2 Ebene 0 | 1113Elg0814016606 | St | Elementgruppe
Geländer+Abstand | H2 Ebene 0 | 1113Elg0814016612 | St | Elementgruppe
Geländer+Abstand | H2 Ebene 0 | 1113Elg0814016624 | St | Elementgruppe
Geländer+Abstand | H2 Ebene 0 | 1113Elg0814016318 | St | Elementgruppe
Geländer+Abstand | H2 Ebene 0 | 1113Elg0814016366 | St | Elementgruppe
Geländer+Abstand | H2 Ebene 0 | 1113Elg0814016138 | St | Elementgruppe
Geländer+Abstand | H2 Ebene 0 | 1113Elg0814016330 | St | Elementgruppe
Geländer+Abstand | H2 Ebene 0 | 1113Elg0814016282 | St | Elementgruppe
Geländer+Abstand | H2 Ebene 0 | 1113Elg0814016516 | St | Elementgruppe
Geländer+Abstand | H2 Ebene 0 | 1113Elg0814016414 | St | Elementgruppe
Geländer+Abstand | H2 Ebene 0 | 1113Elg0814016582 | St | Elementgruppe
Geländer+Abstand | H2 Ebene 0 | 1113Elg0814016144 | St | Elementgruppe
Geländer+Abstand | H2 Ebene 0 | 1113Elg0814019072 | St | Elementgruppe
Geländer+Abstand | H2 Ebene 0 | 1113Elg0814019078 | St | Elementgruppe
Geländer+Abstand | H2 Ebene 0 | 1113Elg0814019090 | St | Elementgruppe
Geländer+Abstand | H2 Ebene 0 | 1113Elg0814019096 | St | Elementgruppe
Geländer+Abstand | H2 Ebene 0 | 1113Elg0814019102 | St | Elementgruppe
Geländer+Abstand | H2 Ebene 0 | 1113Elg0814016510 | St | Elementgruppe
Geländer+Abstand | H2 Ebene 0 | 1113Elg0814016378 | St | Elementgruppe
Geländer+Abstand | H2 Ebene 0 | 1113Elg0814016426 | St | Elementgruppe
Geländer+Abstand | H2 Ebene 0 | 1113Elg0814016228 | St | Elementgruppe | AllplanAttributes - Bezeichnung: Geländer+Abstand
Geländer+Abstand | H2 Ebene 0 | 1113Elg0814016150 | St | Handlauf
Geländer+Abstand | H2 Ebene 0 | 1113Elg0814016156 | St | Handlauf
Geländer+Abstand | H2 Ebene 0 | 1113Elg0814016192 | St | Handlauf
Geländer+Abstand | H2 Ebene 0 | 1113Elg0814016246 | St | Handlauf
Geländer+Abstand | H2 Ebene 0 | 1113Elg0814016252 | St | Handlauf
Geländer+Abstand | H2 Ebene 0 | 1113Elg0814016270 | St | Handlauf
Geländer+Abstand | H2 Ebene 0 | 1113Elg0814016276 | St | Handlauf
Geländer+Abstand | H2 Ebene 0 | 1113Elg0814016486 | St | Handlauf
Geländer+Abstand | H2 Ebene 0 | 1113Elg0814016564 | St | Handlauf
Geländer+Abstand | H2 Ebene 0 | 1113Elg0814016210 | St | Elementgruppe | AllplanAttributes - Bezeichnung: Geländer+Abstand; ash D_Detailverweis: D8; ash D_Plannummer: 1684
Geländer+Abstand | H2 Ebene 0 | 1113Elg0814019084 | St | Elementgruppe

# IfcOpeningElement: Opening (3497)
Name | In | Allright_Bauteil_ID | Abrechnungsart | Versatz_oben | Gewerk | Objektname | Versatz_unten | OKFF | Status | P_ID | AllplanAttributes, Feuerwiderstandsklasse | Sicherheitsklasse | g-Wert
WS | H2 Ebene +4/ Dachebene | 1407Wni0000017825 | m² | 0 | Trockenbauarbeiten | Wandschlitz BKE | 0 | 4.5 | NEW
WS | H2 Ebene +4/ Dachebene | 1407Wni0000017824 | m³ | 0 | Trockenbauarbeiten | Wandschlitz BKE | 0 | 4.5 | NEW
WS | H2 Ebene +4/ Dachebene | 1407Wni0000017823 | m³ | 0 | Trockenbauarbeiten | Wandschlitz BKE | 0 | 4.5 | NEW
WS | H2 Ebene +4/ Dachebene | 1407Wni0000017822 | m² | 0 | Trockenbauarbeiten | Wandschlitz BKE | 0 | 4.5 | NEW
WS | H2 Ebene +4/ Dachebene | 1407Wni0000017821 | m² | 0 | Trockenbauarbeiten | Wandschlitz BKE | 0 | 4.5 | NEW
WS | H2 Ebene +4/ Dachebene | 1407Wni0000017820 | m² | 0 | Trockenbauarbeiten | Wandschlitz BKE | 0 | 4.5 | NEW
WS | H2 Ebene +4/ Dachebene | 1407Wni0000017819 | m² | 0 | Trockenbauarbeiten | Wandschlitz BKE | 0 | 4.5 | NEW
WS | H2 Ebene +4/ Dachebene | 1407Wni0000017583 | m² | 0 | Trockenbauarbeiten | Wandschlitz BKE | 0 | 4.5 | NEW
WS | H2 Ebene +4/ Dachebene | 1407Wni0000017582 | m³ | 0 | Trockenbauarbeiten | Wandschlitz BKE | 0 | 4.5 | NEW
WS | H2 Ebene +4/ Dachebene | 1407Wni0000017581 | m³ | 0 | Trockenbauarbeiten | Wandschlitz BKE | 0 | 4.5 | NEW
WS | H2 Ebene +4/ Dachebene | 1407Wni0000017580 | m² | 0 | Trockenbauarbeiten | Wandschlitz BKE | 0 | 4.5 | NEW
WS | H2 Ebene +4/ Dachebene | 1407Wni0000017579 | m² | 0 | Trockenbauarbeiten | Wandschlitz BKE | 0 | 4.5 | NEW
WS | H2 Ebene +4/ Dachebene | 1407Wni0000017578 | m² | 0 | Trockenbauarbeiten | Wandschlitz BKE | 0 | 4.5 | NEW
WS | H2 Ebene +4/ Dachebene | 1407Wni0000017577 | m² | 0 | Trockenbauarbeiten | Wandschlitz BKE | 0 | 4.5 | NEW
Fensteröffnung | H2 Ebene +3 | 1255Fen0811531341 | m² | 0 | Wärmedämm-Verbundsysteme | Fensteröffnung | 0 | 11.25 | NEW | 1255Wa 0000013072 | AllplanAttributes - Material: Fensterelement; Tragendes Bauteil: no; Brandabschnittsdefinierendes Bauteil: no
Fensteröffnung | H2 Ebene +3 | 1255Fen0811531340 | m³ | 0 | Wärmedämm-Verbundsysteme | Fensteröffnung | 0 | 11.25 | NEW | 1255Wa 0000013071 | AllplanAttributes - Material: Fensterelement; Außenliegend: yes
Fensteröffnung | H2 Ebene +3 | 1255Fen0811531339 | m³ | 0 | Wärmedämm-Verbundsysteme | Fensteröffnung | 0 | 11.25 | NEW | 1255Wa 0000013066
Fensteröffnung | H2 Ebene +3 | 1255Fen0811531338 | m² | 0 | Wärmedämm-Verbundsysteme | Fensteröffnung | 0 | 11.25 | NEW | 1255Wa 0000013069
Fensteröffnung | H2 Ebene +3 | 1255Fen0811531337 | m² | 0 | Wärmedämm-Verbundsysteme | Fensteröffnung | 0 | 11.25 | NEW | 1255Wa 0000013070
Fensteröffnung | H2 Ebene +3 | 1255Fen0811531336 | m² | 0 | Wärmedämm-Verbundsysteme | Fensteröffnung | 0 | 11.25 | NEW | 1255Wa 0000013067
Fensteröffnung | H2 Ebene +3 | 1255Fen0811531335 | m² | 0 | Wärmedämm-Verbundsysteme | Fensteröffnung | 0 | 11.25 | NEW | 1255Wa 0000013068
Fensteröffnung | H2 Ebene +3 | 1255Fen0811530957 | m² |  | Wärmedämm-Verbundsysteme | Fensteröffnung |  | 11.25 | NEW | 1255Wa 0000013072 | AllplanAttributes - Material: Fensterelement; Tragendes Bauteil: no; Brandabschnittsdefinierendes Bauteil: no
Fensteröffnung | H2 Ebene +3 | 1255Fen0811530956 | m³ | 0 | Wärmedämm-Verbundsysteme | Fensteröffnung | 0 | 11.25 | NEW | 1255Wa 0000013071 | AllplanAttributes - Material: Fensterelement; Außenliegend: yes
Fensteröffnung | H2 Ebene +3 | 1255Fen0811530955 | m³ | 0 | Wärmedämm-Verbundsysteme | Fensteröffnung | 0 | 11.25 | NEW | 1255Wa 0000013066
Fensteröffnung | H2 Ebene +3 | 1255Fen0811530954 | m² | 0 | Wärmedämm-Verbundsysteme | Fensteröffnung | 0 | 11.25 | NEW | 1255Wa 0000013069
Fensteröffnung | H2 Ebene +3 | 1255Fen0811530953 | m² | 0 | Wärmedämm-Verbundsysteme | Fensteröffnung | 0 | 11.25 | NEW | 1255Wa 0000013070
Fensteröffnung | H2 Ebene +3 | 1255Fen0811530952 | m² | 0 | Wärmedämm-Verbundsysteme | Fensteröffnung | 0 | 11.25 | NEW | 1255Wa 0000013067
Fensteröffnung | H2 Ebene +3 | 1255Fen0811530951 | m² | 0 | Wärmedämm-Verbundsysteme | Fensteröffnung | 0 | 11.25 | NEW | 1255Wa 0000013068
Fensteröffnung | H2 Ebene +3 | 1255Fen0000013062 | m² |  | Wärmedämm-Verbundsysteme | Fensteröffnung |  | 11.25 | NEW | 1255Wa 0000013072 | AllplanAttributes - Material: Fensterelement; Tragendes Bauteil: no; Brandabschnittsdefinierendes Bauteil: no
Fensteröffnung | H2 Ebene +3 | 1255Fen0000013061 | m³ | 0 | Wärmedämm-Verbundsysteme | Fensteröffnung | 0 | 11.25 | NEW | 1255Wa 0000013071 | AllplanAttributes - Material: Fensterelement; Außenliegend: yes
Fensteröffnung | H2 Ebene +3 | 1255Fen0000013060 | m³ | 0 | Wärmedämm-Verbundsysteme | Fensteröffnung | 0 | 11.25 | NEW | 1255Wa 0000013066
Fensteröffnung | H2 Ebene +3 | 1255Fen0000013059 | m² | 0 | Wärmedämm-Verbundsysteme | Fensteröffnung | 0 | 11.25 | NEW | 1255Wa 0000013069
Fensteröffnung | H2 Ebene +3 | 1255Fen0000013058 | m² | 0 | Wärmedämm-Verbundsysteme | Fensteröffnung | 0 | 11.25 | NEW | 1255Wa 0000013070
Fensteröffnung | H2 Ebene +3 | 1255Fen0000013057 | m² | 0 | Wärmedämm-Verbundsysteme | Fensteröffnung | 0 | 11.25 | NEW | 1255Wa 0000013067
Fensteröffnung | H2 Ebene +3 | 1255Fen0000013056 | m² | 0 | Wärmedämm-Verbundsysteme | Fensteröffnung | 0 | 11.25 | NEW | 1255Wa 0000013068
Fensteröffnung | H2 Ebene +3 | 1255Fen0000000932 | m² |  | Wärmedämm-Verbundsysteme | Fensteröffnung |  | 11.25 | NEW | 1255Wa 0000001000 | AllplanAttributes - Material: Fensterelement; Tragendes Bauteil: no; Brandabschnittsdefinierendes Bauteil: no; ash D_Detailverweis: FS TR; ash D_Plannummer: D1530
Fensteröffnung | H2 Ebene +3 | 1255Fen0000000921 | m³ | 0 | Wärmedämm-Verbundsysteme | Fensteröffnung | 0 | 11.25 | NEW | 1255Wa 0000000993 | AllplanAttributes - Material: Fensterelement; Außenliegend: yes
Fensteröffnung | H2 Ebene +3 | 1255Fen0000000919 | m² | 0 | Wärmedämm-Verbundsysteme | Fensteröffnung | 0 | 11.25 | NEW | 1255Wa 0000000986
Fensteröffnung | H2 Ebene +3 | 1255Fen0000000917 | m² | 0 | Wärmedämm-Verbundsysteme | Fensteröffnung | 0 | 11.25 | NEW | 1255Wa 0000000979
Fensteröffnung | H2 Ebene +3 | 1255Fen0000000915 | m² | 0 | Wärmedämm-Verbundsysteme | Fensteröffnung | 0 | 11.25 | NEW | 1255Wa 0000000972
Fensteröffnung | H2 Ebene +3 | 1255Fen0811400410 | m² | 0 | Wärmedämm-Verbundsysteme | Fensteröffnung | 0 | 11.25 | NEW | 1255Wa 0811400273
Fensteröffnung | H2 Ebene +3 | 1255Fen0811531383 | m² | 0 | Wärmedämm-Verbundsysteme | Fensteröffnung | 0 | 11.25 | NEW | 1255Wa 0000013072 | AllplanAttributes - Material: Fensterelement; Tragendes Bauteil: no; Brandabschnittsdefinierendes Bauteil: no
Fensteröffnung | H2 Ebene +3 | 1255Fen0811531382 | m³ | 0 | Wärmedämm-Verbundsysteme | Fensteröffnung | 0 | 11.25 | NEW | 1255Wa 0000013071 | AllplanAttributes - Material: Fensterelement; Außenliegend: yes
Fensteröffnung | H2 Ebene +3 | 1255Fen0811531381 | m³ | 0 | Wärmedämm-Verbundsysteme | Fensteröffnung | 0 | 11.25 | NEW | 1255Wa 0000013066
Fensteröffnung | H2 Ebene +3 | 1255Fen0811531380 | m² | 0 | Wärmedämm-Verbundsysteme | Fensteröffnung | 0 | 11.25 | NEW | 1255Wa 0000013069
Fensteröffnung | H2 Ebene +3 | 1255Fen0811531379 | m² | 0 | Wärmedämm-Verbundsysteme | Fensteröffnung | 0 | 11.25 | NEW | 1255Wa 0000013070
Fensteröffnung | H2 Ebene +3 | 1255Fen0811531378 | m² | 0 | Wärmedämm-Verbundsysteme | Fensteröffnung | 0 | 11.25 | NEW | 1255Wa 0000013067
Fensteröffnung | H2 Ebene +3 | 1255Fen0811531377 | m² | 0 | Wärmedämm-Verbundsysteme | Fensteröffnung | 0 | 11.25 | NEW | 1255Wa 0000013068
Fensteröffnung | H2 Ebene +3 | 1255Fen0811531425 | m² | 0 | Wärmedämm-Verbundsysteme | Fensteröffnung | 0 | 11.25 | NEW | 1255Wa 0000013072 | AllplanAttributes - Material: Fensterelement; Tragendes Bauteil: no; Brandabschnittsdefinierendes Bauteil: no
Fensteröffnung | H2 Ebene +3 | 1255Fen0811531467 | m² | 0 | Wärmedämm-Verbundsysteme | Fensteröffnung | 0 | 11.25 | NEW | 1255Wa 0000013072 | AllplanAttributes - Material: Fensterelement; Tragendes Bauteil: no; Brandabschnittsdefinierendes Bauteil: no
Fensteröffnung | H2 Ebene +3 | 1255Fen0811531424 | m³ | 0 | Wärmedämm-Verbundsysteme | Fensteröffnung | 0 | 11.25 | NEW | 1255Wa 0000013071 | AllplanAttributes - Material: Fensterelement; Außenliegend: yes
Fensteröffnung | H2 Ebene +3 | 1255Fen0811531466 | m³ | 0 | Wärmedämm-Verbundsysteme | Fensteröffnung | 0 | 11.25 | NEW | 1255Wa 0000013071 | AllplanAttributes - Material: Fensterelement; Außenliegend: yes
Fensteröffnung | H2 Ebene +3 | 1255Fen0811531423 | m³ | 0 | Wärmedämm-Verbundsysteme | Fensteröffnung | 0 | 11.25 | NEW | 1255Wa 0000013066
Fensteröffnung | H2 Ebene +3 | 1255Fen0811531465 | m³ | 0 | Wärmedämm-Verbundsysteme | Fensteröffnung | 0 | 11.25 | NEW | 1255Wa 0000013066
Fensteröffnung | H2 Ebene +3 | 1255Fen0811531422 | m² | 0 | Wärmedämm-Verbundsysteme | Fensteröffnung | 0 | 11.25 | NEW | 1255Wa 0000013069
Fensteröffnung | H2 Ebene +3 | 1255Fen0811531464 | m² | 0 | Wärmedämm-Verbundsysteme | Fensteröffnung | 0 | 11.25 | NEW | 1255Wa 0000013069
Fensteröffnung | H2 Ebene +3 | 1255Fen0811531421 | m² | 0 | Wärmedämm-Verbundsysteme | Fensteröffnung | 0 | 11.25 | NEW | 1255Wa 0000013070
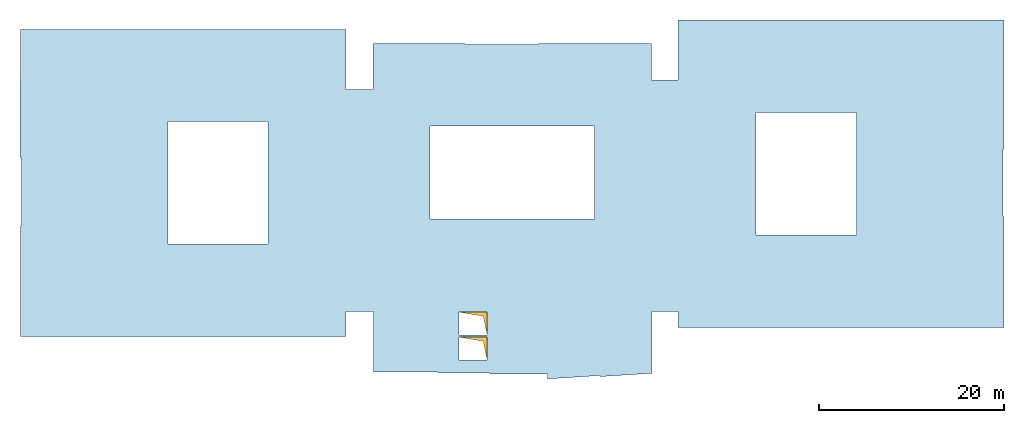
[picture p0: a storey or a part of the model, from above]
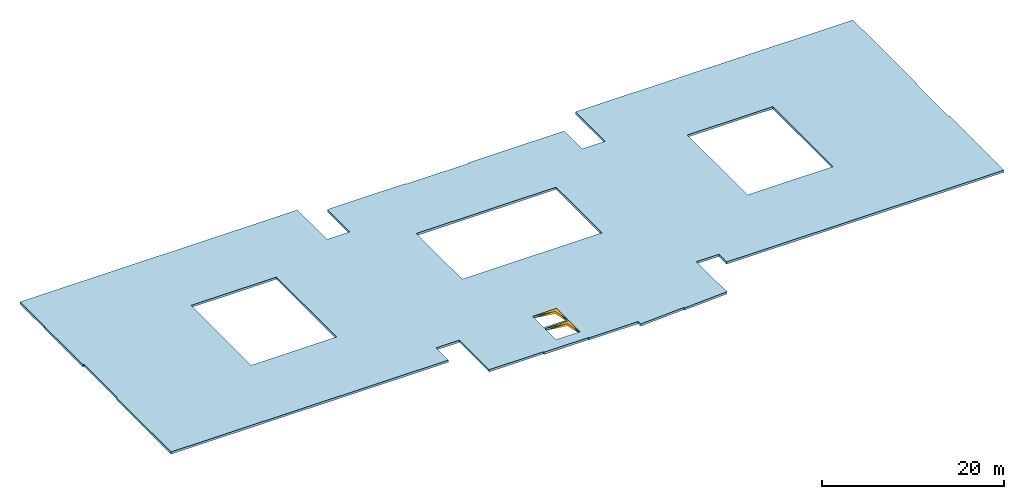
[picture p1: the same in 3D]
Properties of the parts of a building model (IFC4), part 29 of 80

# IfcOpeningElement: Opening (3497)
Name | In | Allright_Bauteil_ID | Abrechnungsart | Versatz_oben | Gewerk | Objektname | Versatz_unten | OKFF | Status | P_ID | AllplanAttributes, Feuerwiderstandsklasse | Sicherheitsklasse | g-Wert
Fensteröffnung | H2 Ebene +3 | 1255Fen0811531463 | m² | 0 | Wärmedämm-Verbundsysteme | Fensteröffnung | 0 | 11.25 | NEW | 1255Wa 0000013070
Fensteröffnung | H2 Ebene +3 | 1255Fen0811531420 | m² | 0 | Wärmedämm-Verbundsysteme | Fensteröffnung | 0 | 11.25 | NEW | 1255Wa 0000013067
Fensteröffnung | H2 Ebene +3 | 1255Fen0811531462 | m² | 0 | Wärmedämm-Verbundsysteme | Fensteröffnung | 0 | 11.25 | NEW | 1255Wa 0000013067
Fensteröffnung | H2 Ebene +3 | 1255Fen0811531419 | m² | 0 | Wärmedämm-Verbundsysteme | Fensteröffnung | 0 | 11.25 | NEW | 1255Wa 0000013068
Fensteröffnung | H2 Ebene +3 | 1255Fen0811531461 | m² | 0 | Wärmedämm-Verbundsysteme | Fensteröffnung | 0 | 11.25 | NEW | 1255Wa 0000013068
Fensteröffnung | H2 Ebene +3 | 1255Fen0811534195 | m² | 0 | Wärmedämm-Verbundsysteme | Fensteröffnung | 0 | 11.25 | NEW | 1255Wa 0000000843 | AllplanAttributes - Material: Fensterelement; Tragendes Bauteil: no; Brandabschnittsdefinierendes Bauteil: no
Fensteröffnung | H2 Ebene +3 | 1255Fen0811534382 | m² | 0 | Wärmedämm-Verbundsysteme | Fensteröffnung | 0 | 11.25 | NEW | 1255Wa 0000000843 | AllplanAttributes - Material: Fensterelement; Tragendes Bauteil: no; Brandabschnittsdefinierendes Bauteil: no
Fensteröffnung | H2 Ebene +3 | 1255Fen0811534439 | m² | 0 | Wärmedämm-Verbundsysteme | Fensteröffnung | 0 | 11.25 | NEW | 1255Wa 0000000843 | AllplanAttributes - Material: Fensterelement; Tragendes Bauteil: no; Brandabschnittsdefinierendes Bauteil: no
Fensteröffnung | H2 Ebene +3 | 1255Fen0811534325 | m² | 0 | Wärmedämm-Verbundsysteme | Fensteröffnung | 0 | 11.25 | NEW | 1255Wa 0000000843 | AllplanAttributes - Material: Fensterelement; Tragendes Bauteil: no; Brandabschnittsdefinierendes Bauteil: no
Fensteröffnung | H2 Ebene +3 | 1255Fen0811534268 | m² | 0 | Wärmedämm-Verbundsysteme | Fensteröffnung | 0 | 11.25 | NEW | 1255Wa 0000000843 | AllplanAttributes - Material: Fensterelement; Tragendes Bauteil: no; Brandabschnittsdefinierendes Bauteil: no
Fensteröffnung | H2 Ebene +3 | 1255Fen0811534194 | m³ | 0 | Wärmedämm-Verbundsysteme | Fensteröffnung | 0 | 11.25 | NEW | 1255Wa 0000001556 | AllplanAttributes - Material: Fensterelement; Außenliegend: yes
Fensteröffnung | H2 Ebene +3 | 1255Fen0811534381 | m³ | 0 | Wärmedämm-Verbundsysteme | Fensteröffnung | 0 | 11.25 | NEW | 1255Wa 0000001556 | AllplanAttributes - Material: Fensterelement; Außenliegend: yes
Fensteröffnung | H2 Ebene +3 | 1255Fen0811534438 | m³ | 0 | Wärmedämm-Verbundsysteme | Fensteröffnung | 0 | 11.25 | NEW | 1255Wa 0000001556 | AllplanAttributes - Material: Fensterelement; Außenliegend: yes
Fensteröffnung | H2 Ebene +3 | 1255Fen0811534324 | m³ | 0 | Wärmedämm-Verbundsysteme | Fensteröffnung | 0 | 11.25 | NEW | 1255Wa 0000001556 | AllplanAttributes - Material: Fensterelement; Außenliegend: yes
2 x Fensteröffnung | H2 Ebene +3 | 1255Fen0811534266 | m³ | 0 | Wärmedämm-Verbundsysteme | Fensteröffnung | 0 | 11.25 | NEW | 1255Wa 0000001548
Fensteröffnung | H2 Ebene +3 | 1255Fen0811534267 | m³ | 0 | Wärmedämm-Verbundsysteme | Fensteröffnung | 0 | 11.25 | NEW | 1255Wa 0000001556 | AllplanAttributes - Material: Fensterelement; Außenliegend: yes
Fensteröffnung | H2 Ebene +3 | 1255Fen0811534193 | m³ | 0 | Wärmedämm-Verbundsysteme | Fensteröffnung | 0 | 11.25 | NEW | 1255Wa 0000001548
Fensteröffnung | H2 Ebene +3 | 1255Fen0811534380 | m³ | 0 | Wärmedämm-Verbundsysteme | Fensteröffnung | 0 | 11.25 | NEW | 1255Wa 0000001548
Fensteröffnung | H2 Ebene +3 | 1255Fen0811534437 | m³ | 0 | Wärmedämm-Verbundsysteme | Fensteröffnung | 0 | 11.25 | NEW | 1255Wa 0000001548
Fensteröffnung | H2 Ebene +3 | 1255Fen0811534323 | m³ | 0 | Wärmedämm-Verbundsysteme | Fensteröffnung | 0 | 11.25 | NEW | 1255Wa 0000001548
2 x Fensteröffnung | H2 Ebene +3 | 1255Fen0811534265 | m³ | 0 | Wärmedämm-Verbundsysteme | Fensteröffnung | 0 | 11.25 | NEW | 1255Wa 0000001540
Fensteröffnung | H2 Ebene +3 | 1255Fen0811534192 | m³ | 0 | Wärmedämm-Verbundsysteme | Fensteröffnung | 0 | 11.25 | NEW | 1255Wa 0000001540
Fensteröffnung | H2 Ebene +3 | 1255Fen0811534322 | m³ | 0 | Wärmedämm-Verbundsysteme | Fensteröffnung | 0 | 11.25 | NEW | 1255Wa 0000001540
Fensteröffnung | H2 Ebene +3 | 1255Fen0811534379 | m³ | 0 | Wärmedämm-Verbundsysteme | Fensteröffnung | 0 | 11.25 | NEW | 1255Wa 0000001540
Fensteröffnung | H2 Ebene +3 | 1255Fen0811534436 | m³ | 0 | Wärmedämm-Verbundsysteme | Fensteröffnung | 0 | 11.25 | NEW | 1255Wa 0000001540
Fensteröffnung | H2 Ebene +3 | 1255Fen0811534191 | m² | 0 | Wärmedämm-Verbundsysteme | Fensteröffnung | 0 | 11.25 | NEW | 1255Wa 0000001532
Fensteröffnung | H2 Ebene +3 | 1255Fen0811534378 | m² | 0 | Wärmedämm-Verbundsysteme | Fensteröffnung | 0 | 11.25 | NEW | 1255Wa 0000001532
Fensteröffnung | H2 Ebene +3 | 1255Fen0811534435 | m² | 0 | Wärmedämm-Verbundsysteme | Fensteröffnung | 0 | 11.25 | NEW | 1255Wa 0000001532
Fensteröffnung | H2 Ebene +3 | 1255Fen0811534321 | m² | 0 | Wärmedämm-Verbundsysteme | Fensteröffnung | 0 | 11.25 | NEW | 1255Wa 0000001532
Fensteröffnung | H2 Ebene +3 | 1255Fen0811534264 | m² | 0 | Wärmedämm-Verbundsysteme | Fensteröffnung | 0 | 11.25 | NEW | 1255Wa 0000001532
Fensteröffnung | H2 Ebene +3 | 1255Fen0811534190 | m² | 0 | Wärmedämm-Verbundsysteme | Fensteröffnung | 0 | 11.25 | NEW | 1255Wa 0000001524
Fensteröffnung | H2 Ebene +3 | 1255Fen0811534377 | m² | 0 | Wärmedämm-Verbundsysteme | Fensteröffnung | 0 | 11.25 | NEW | 1255Wa 0000001524
Fensteröffnung | H2 Ebene +3 | 1255Fen0811534434 | m² | 0 | Wärmedämm-Verbundsysteme | Fensteröffnung | 0 | 11.25 | NEW | 1255Wa 0000001524
Fensteröffnung | H2 Ebene +3 | 1255Fen0811534320 | m² | 0 | Wärmedämm-Verbundsysteme | Fensteröffnung | 0 | 11.25 | NEW | 1255Wa 0000001524
Fensteröffnung | H2 Ebene +3 | 1255Fen0811534263 | m² | 0 | Wärmedämm-Verbundsysteme | Fensteröffnung | 0 | 11.25 | NEW | 1255Wa 0000001524
Fensteröffnung | H2 Ebene +3 | 1255Fen0811534189 | m² | 0 | Wärmedämm-Verbundsysteme | Fensteröffnung | 0 | 11.25 | NEW | 1255Wa 0000001516
Fensteröffnung | H2 Ebene +3 | 1255Fen0811534376 | m² | 0 | Wärmedämm-Verbundsysteme | Fensteröffnung | 0 | 11.25 | NEW | 1255Wa 0000001516
Fensteröffnung | H2 Ebene +3 | 1255Fen0811534433 | m² | 0 | Wärmedämm-Verbundsysteme | Fensteröffnung | 0 | 11.25 | NEW | 1255Wa 0000001516
Fensteröffnung | H2 Ebene +3 | 1255Fen0811534319 | m² | 0 | Wärmedämm-Verbundsysteme | Fensteröffnung | 0 | 11.25 | NEW | 1255Wa 0000001516
Fensteröffnung | H2 Ebene +3 | 1255Fen0811534262 | m² | 0 | Wärmedämm-Verbundsysteme | Fensteröffnung | 0 | 11.25 | NEW | 1255Wa 0000001516
Fensteröffnung | H2 Ebene +3 | 1255Fen0811534261 | m² | 0 | Wärmedämm-Verbundsysteme | Fensteröffnung | 0 | 11.25 | NEW | 1255Wa 0811474006
Fensteröffnung | H2 Ebene +3 | 1255Fen0811534318 | m² | 0 | Wärmedämm-Verbundsysteme | Fensteröffnung | 0 | 11.25 | NEW | 1255Wa 0811474006
Fensteröffnung | H2 Ebene +3 | 1255Fen0811534432 | m² | 0 | Wärmedämm-Verbundsysteme | Fensteröffnung | 0 | 11.25 | NEW | 1255Wa 0811474006
Fensteröffnung | H2 Ebene +3 | 1255Fen0811534375 | m² | 0 | Wärmedämm-Verbundsysteme | Fensteröffnung | 0 | 11.25 | NEW | 1255Wa 0811474006
Fensteröffnung | H2 Ebene +3 | 1255Fen0811534188 | m² | 0 | Wärmedämm-Verbundsysteme | Fensteröffnung | 0 | 11.25 | NEW | 1255Wa 0811474006
Fensteröffnung | H2 Ebene +3 | 1255Fen0811533823 | m² | 0 | Wärmedämm-Verbundsysteme | Fensteröffnung | 0 | 11.25 | NEW | 1255Wa 0000000843 | AllplanAttributes - Material: Fensterelement; Tragendes Bauteil: no; Brandabschnittsdefinierendes Bauteil: no
Fensteröffnung | H2 Ebene +3 | 1255Fen0811533822 | m³ | 0 | Wärmedämm-Verbundsysteme | Fensteröffnung | 0 | 11.25 | NEW | 1255Wa 0000001556 | AllplanAttributes - Material: Fensterelement; Außenliegend: yes
Fensteröffnung | H2 Ebene +3 | 1255Fen0811533821 | m³ | 0 | Wärmedämm-Verbundsysteme | Fensteröffnung | 0 | 11.25 | NEW | 1255Wa 0000001548
Fensteröffnung | H2 Ebene +3 | 1255Fen0811533820 | m³ | 0 | Wärmedämm-Verbundsysteme | Fensteröffnung | 0 | 11.25 | NEW | 1255Wa 0000001540
Fensteröffnung | H2 Ebene +3 | 1255Fen0811533819 | m² | 0 | Wärmedämm-Verbundsysteme | Fensteröffnung | 0 | 11.25 | NEW | 1255Wa 0000001532
Fensteröffnung | H2 Ebene +3 | 1255Fen0811533818 | m² | 0 | Wärmedämm-Verbundsysteme | Fensteröffnung | 0 | 11.25 | NEW | 1255Wa 0000001524
Fensteröffnung | H2 Ebene +3 | 1255Fen0811533817 | m² | 0 | Wärmedämm-Verbundsysteme | Fensteröffnung | 0 | 11.25 | NEW | 1255Wa 0000001516
Fensteröffnung | H2 Ebene +3 | 1255Fen0811533816 | m² | 0 | Wärmedämm-Verbundsysteme | Fensteröffnung | 0 | 11.25 | NEW | 1255Wa 0811474006
Fensteröffnung | H2 Ebene +3 | 1255Fen0811596269 | m² |  | Wärmedämm-Verbundsysteme | Fensteröffnung |  | 11.25 | NEW | 1255Wa 0000013072 | AllplanAttributes - Material: Fensterelement; Tragendes Bauteil: no; Brandabschnittsdefinierendes Bauteil: no
Fensteröffnung | H2 Ebene +3 | 1255Fen0811596268 | m³ | 0 | Wärmedämm-Verbundsysteme | Fensteröffnung | 0 | 11.25 | NEW | 1255Wa 0000013071 | AllplanAttributes - Material: Fensterelement; Außenliegend: yes
Fensteröffnung | H2 Ebene +3 | 1255Fen0811596267 | m³ | 0 | Wärmedämm-Verbundsysteme | Fensteröffnung | 0 | 11.25 | NEW | 1255Wa 0000013066
Fensteröffnung | H2 Ebene +3 | 1255Fen0811596266 | m² | 0 | Wärmedämm-Verbundsysteme | Fensteröffnung | 0 | 11.25 | NEW | 1255Wa 0000013069
Fensteröffnung | H2 Ebene +3 | 1255Fen0811596265 | m² | 0 | Wärmedämm-Verbundsysteme | Fensteröffnung | 0 | 11.25 | NEW | 1255Wa 0000013070
Fensteröffnung | H2 Ebene +3 | 1255Fen0811596264 | m² | 0 | Wärmedämm-Verbundsysteme | Fensteröffnung | 0 | 11.25 | NEW | 1255Wa 0000013067
Fensteröffnung | H2 Ebene +3 | 1255Fen0811596263 | m² | 0 | Wärmedämm-Verbundsysteme | Fensteröffnung | 0 | 11.25 | NEW | 1255Wa 0000013068
Fensteröffnung | H2 Ebene +3 | 1255Fen0811596390 | m² |  | Wärmedämm-Verbundsysteme | Fensteröffnung |  | 11.25 | NEW | 1255Wa 0000013072 | AllplanAttributes - Material: Fensterelement; Tragendes Bauteil: no; Brandabschnittsdefinierendes Bauteil: no
Fensteröffnung | H2 Ebene +3 | 1255Fen0811596389 | m³ | 0 | Wärmedämm-Verbundsysteme | Fensteröffnung | 0 | 11.25 | NEW | 1255Wa 0000013071 | AllplanAttributes - Material: Fensterelement; Außenliegend: yes
Fensteröffnung | H2 Ebene +3 | 1255Fen0811596388 | m³ | 0 | Wärmedämm-Verbundsysteme | Fensteröffnung | 0 | 11.25 | NEW | 1255Wa 0000013066
Fensteröffnung | H2 Ebene +3 | 1255Fen0811596387 | m² | 0 | Wärmedämm-Verbundsysteme | Fensteröffnung | 0 | 11.25 | NEW | 1255Wa 0000013069
Fensteröffnung | H2 Ebene +3 | 1255Fen0811596386 | m² | 0 | Wärmedämm-Verbundsysteme | Fensteröffnung | 0 | 11.25 | NEW | 1255Wa 0000013070
Fensteröffnung | H2 Ebene +3 | 1255Fen0811596385 | m² | 0 | Wärmedämm-Verbundsysteme | Fensteröffnung | 0 | 11.25 | NEW | 1255Wa 0000013067
Fensteröffnung | H2 Ebene +3 | 1255Fen0811596384 | m² | 0 | Wärmedämm-Verbundsysteme | Fensteröffnung | 0 | 11.25 | NEW | 1255Wa 0000013068
Fensteröffnung | H2 Ebene +3 | 1255Fen0811536811 | m² |  | Wärmedämm-Verbundsysteme | Fensteröffnung |  | 11.25 | NEW | 1255Wa 0000001668 | 0 | AllplanAttributes - Material: Fensterelement; Tragendes Bauteil: no; Brandabschnittsdefinierendes Bauteil: no
Fensteröffnung | H2 Ebene +3 | 1255Fen0811536810 | m³ | 0 | Wärmedämm-Verbundsysteme | Fensteröffnung | 0 | 11.25 | NEW | 1255Wa 0000001664 | 0 | AllplanAttributes - Material: Fensterelement; Außenliegend: yes
Fensteröffnung | H2 Ebene +3 | 1255Fen0811536809 | m³ | 0 | Wärmedämm-Verbundsysteme | Fensteröffnung | 0 | 11.25 | NEW | 1255Wa 0000001660 | 0
Fensteröffnung | H2 Ebene +3 | 1255Fen0811536808 | m² | 0 | Wärmedämm-Verbundsysteme | Fensteröffnung | 0 | 11.25 | NEW | 1255Wa 0000001656 | 0
Fensteröffnung | H2 Ebene +3 | 1255Fen0811536807 | m² | 0 | Wärmedämm-Verbundsysteme | Fensteröffnung | 0 | 11.25 | NEW | 1255Wa 0000001652 | 0
Fensteröffnung | H2 Ebene +3 | 1255Fen0811536806 | m² | 0 | Wärmedämm-Verbundsysteme | Fensteröffnung | 0 | 11.25 | NEW | 1255Wa 0000001648 | 0
Fensteröffnung | H2 Ebene +3 | 1255Fen0811536805 | m² | 0 | Wärmedämm-Verbundsysteme | Fensteröffnung | 0 | 11.25 | NEW | 1255Wa 0000001644 | 0
Fensteröffnung | H2 Ebene +3 | 1255Fen0811537731 | m² |  | Wärmedämm-Verbundsysteme | Fensteröffnung |  | 11.25 | NEW | 1255Wa 0000001561 | AllplanAttributes - Material: Fensterelement; Tragendes Bauteil: no; Brandabschnittsdefinierendes Bauteil: no
Fensteröffnung | H2 Ebene +3 | 1255Fen0811537647 | m² |  | Wärmedämm-Verbundsysteme | Fensteröffnung |  | 11.25 | NEW | 1255Wa 0000001561 | AllplanAttributes - Material: Fensterelement; Tragendes Bauteil: no; Brandabschnittsdefinierendes Bauteil: no
Fensteröffnung | H2 Ebene +3 | 1255Fen0811537730 | m³ | 0 | Wärmedämm-Verbundsysteme | Fensteröffnung | 0 | 11.25 | NEW | 1255Wa 0000001492 | AllplanAttributes - Material: Fensterelement; Außenliegend: yes
Fensteröffnung | H2 Ebene +3 | 1255Fen0811537646 | m³ | 0 | Wärmedämm-Verbundsysteme | Fensteröffnung | 0 | 11.25 | NEW | 1255Wa 0000001492 | AllplanAttributes - Material: Fensterelement; Außenliegend: yes
Fensteröffnung | H2 Ebene +3 | 1255Fen0811537729 | m³ | 0 | Wärmedämm-Verbundsysteme | Fensteröffnung | 0 | 11.25 | NEW | 1255Wa 0000001496
Fensteröffnung | H2 Ebene +3 | 1255Fen0811537645 | m³ | 0 | Wärmedämm-Verbundsysteme | Fensteröffnung | 0 | 11.25 | NEW | 1255Wa 0000001496
Fensteröffnung | H2 Ebene +3 | 1255Fen0811537728 | m² | 0 | Wärmedämm-Verbundsysteme | Fensteröffnung | 0 | 11.25 | NEW | 1255Wa 0000001500
Fensteröffnung | H2 Ebene +3 | 1255Fen0811537644 | m² | 0 | Wärmedämm-Verbundsysteme | Fensteröffnung | 0 | 11.25 | NEW | 1255Wa 0000001500
Fensteröffnung | H2 Ebene +3 | 1255Fen0811537727 | m² | 0 | Wärmedämm-Verbundsysteme | Fensteröffnung | 0 | 11.25 | NEW | 1255Wa 0000001504
Fensteröffnung | H2 Ebene +3 | 1255Fen0811537643 | m² | 0 | Wärmedämm-Verbundsysteme | Fensteröffnung | 0 | 11.25 | NEW | 1255Wa 0000001504
Fensteröffnung | H2 Ebene +3 | 1255Fen0811537726 | m² | 0 | Wärmedämm-Verbundsysteme | Fensteröffnung | 0 | 11.25 | NEW | 1255Wa 0000001508
Fensteröffnung | H2 Ebene +3 | 1255Fen0811537642 | m² | 0 | Wärmedämm-Verbundsysteme | Fensteröffnung | 0 | 11.25 | NEW | 1255Wa 0000001508
Fensteröffnung | H2 Ebene +3 | 1255Fen0811537725 | m² | 0 | Wärmedämm-Verbundsysteme | Fensteröffnung | 0 | 11.25 | NEW | 1255Wa 0000001488
Fensteröffnung | H2 Ebene +3 | 1255Fen0811537641 | m² | 0 | Wärmedämm-Verbundsysteme | Fensteröffnung | 0 | 11.25 | NEW | 1255Wa 0000001488
Fensteröffnung | H2 Ebene +3 | 1255Fen0811535762 | m² |  | Wärmedämm-Verbundsysteme | Fensteröffnung |  | 11.25 | NEW | 1255Wa 0000001561 | AllplanAttributes - Material: Fensterelement; Tragendes Bauteil: no; Brandabschnittsdefinierendes Bauteil: no
Fensteröffnung | H2 Ebene +3 | 1255Fen0811535623 | m² |  | Wärmedämm-Verbundsysteme | Fensteröffnung |  | 11.25 | NEW | 1255Wa 0000001561 | AllplanAttributes - Material: Fensterelement; Tragendes Bauteil: no; Brandabschnittsdefinierendes Bauteil: no
Fensteröffnung | H2 Ebene +3 | 1255Fen0811535761 | m³ | 0 | Wärmedämm-Verbundsysteme | Fensteröffnung | 0 | 11.25 | NEW | 1255Wa 0000001492 | AllplanAttributes - Material: Fensterelement; Außenliegend: yes
Fensteröffnung | H2 Ebene +3 | 1255Fen0811535622 | m³ | 0 | Wärmedämm-Verbundsysteme | Fensteröffnung | 0 | 11.25 | NEW | 1255Wa 0000001492 | AllplanAttributes - Material: Fensterelement; Außenliegend: yes
Fensteröffnung | H2 Ebene +3 | 1255Fen0811535760 | m³ | 0 | Wärmedämm-Verbundsysteme | Fensteröffnung | 0 | 11.25 | NEW | 1255Wa 0000001496
Fensteröffnung | H2 Ebene +3 | 1255Fen0811535621 | m³ | 0 | Wärmedämm-Verbundsysteme | Fensteröffnung | 0 | 11.25 | NEW | 1255Wa 0000001496
Fensteröffnung | H2 Ebene +3 | 1255Fen0811535759 | m² | 0 | Wärmedämm-Verbundsysteme | Fensteröffnung | 0 | 11.25 | NEW | 1255Wa 0000001500
Fensteröffnung | H2 Ebene +3 | 1255Fen0811535620 | m² | 0 | Wärmedämm-Verbundsysteme | Fensteröffnung | 0 | 11.25 | NEW | 1255Wa 0000001500
Fensteröffnung | H2 Ebene +3 | 1255Fen0811535758 | m² | 0 | Wärmedämm-Verbundsysteme | Fensteröffnung | 0 | 11.25 | NEW | 1255Wa 0000001504
Fensteröffnung | H2 Ebene +3 | 1255Fen0811535619 | m² | 0 | Wärmedämm-Verbundsysteme | Fensteröffnung | 0 | 11.25 | NEW | 1255Wa 0000001504
Fensteröffnung | H2 Ebene +3 | 1255Fen0811535757 | m² | 0 | Wärmedämm-Verbundsysteme | Fensteröffnung | 0 | 11.25 | NEW | 1255Wa 0000001508
Fensteröffnung | H2 Ebene +3 | 1255Fen0811535618 | m² | 0 | Wärmedämm-Verbundsysteme | Fensteröffnung | 0 | 11.25 | NEW | 1255Wa 0000001508
Fensteröffnung | H2 Ebene +3 | 1255Fen0811535756 | m² | 0 | Wärmedämm-Verbundsysteme | Fensteröffnung | 0 | 11.25 | NEW | 1255Wa 0000001488
Fensteröffnung | H2 Ebene +3 | 1255Fen0811535617 | m² | 0 | Wärmedämm-Verbundsysteme | Fensteröffnung | 0 | 11.25 | NEW | 1255Wa 0000001488
Fensteröffnung | H2 Ebene +3 | 1255Fen0000001272 | m² |  | Wärmedämm-Verbundsysteme | Fensteröffnung |  | 11.25 | NEW | 1255Wa 0000001291 | AllplanAttributes - Material: Fensterelement; Tragendes Bauteil: no; Brandabschnittsdefinierendes Bauteil: no
Fensteröffnung | H2 Ebene +3 | 1255Fen0000001274 | m³ | 0 | Wärmedämm-Verbundsysteme | Fensteröffnung | 0 | 11.25 | NEW | 1255Wa 0000001345 | AllplanAttributes - Material: Fensterelement; Außenliegend: yes
Fensteröffnung | H2 Ebene +3 | 1255Fen0000001276 | m³ | 0 | Wärmedämm-Verbundsysteme | Fensteröffnung | 0 | 11.25 | NEW | 1255Wa 0000001335
Fensteröffnung | H2 Ebene +3 | 1255Fen0000001278 | m² | 0 | Wärmedämm-Verbundsysteme | Fensteröffnung | 0 | 11.25 | NEW | 1255Wa 0000001324
Fensteröffnung | H2 Ebene +3 | 1255Fen0000001280 | m² | 0 | Wärmedämm-Verbundsysteme | Fensteröffnung | 0 | 11.25 | NEW | 1255Wa 0000001313
Fensteröffnung | H2 Ebene +3 | 1255Fen0000001282 | m² | 0 | Wärmedämm-Verbundsysteme | Fensteröffnung | 0 | 11.25 | NEW | 1255Wa 0000001302
Fensteröffnung | H2 Ebene +3 | 1255Fen0000001284 | m² | 0 | Wärmedämm-Verbundsysteme | Fensteröffnung | 0 | 11.25 | NEW | 1255Wa 0000001355
Fensteröffnung | H2 Ebene +3 | 1255Fen0811529575 | m² |  | Fensterarbeiten | Fensteröffnung |  | 11.25 |  | 1205Wa 0000102069 | 0 | - | 0,51 | AllplanAttributes - ash D_Detailverweis: <undefiniert>; U-Wert: 0.9; Schallschutzklasse: 32; Sonnenschutztyp: Movable
Fensteröffnung | H2 Ebene +3 | 1255Fen0811529588 | m³ | 0 | Fensterarbeiten | Fensteröffnung | 0 | 11.25 |  | 1205Wa 0000102066 | 0 | - | 0,51 | AllplanAttributes - ash D_Detailverweis: <undefiniert>; U-Wert: 0.9; Schallschutzklasse: 32; Sonnenschutztyp: Movable
Fensteröffnung | H2 Ebene +3 | 1255Fen0811529586 | m³ | 0 | Fensterarbeiten | Fensteröffnung | 0 | 11.25 |  | 1205Wa 0000102063 | 0 | - | 0,51 | AllplanAttributes - ash D_Detailverweis: <undefiniert>; U-Wert: 0.9; Schallschutzklasse: 32; Sonnenschutztyp: Movable
Fensteröffnung | H2 Ebene +3 | 1255Fen0811529584 | m² | 0 | Fensterarbeiten | Fensteröffnung | 0 | 11.25 |  | 1205Wa 0000102060 | 0 | - | 0,51 | AllplanAttributes - ash D_Detailverweis: <undefiniert>; U-Wert: 0.9; Schallschutzklasse: 32; Sonnenschutztyp: Movable
Fensteröffnung | H2 Ebene +3 | 1255Fen0811529582 | m² | 0 | Fensterarbeiten | Fensteröffnung | 0 | 11.25 | NEW | 1205Wa 0000102057 | 0 | - | 0,51 | AllplanAttributes - ash D_Detailverweis: <undefiniert>; U-Wert: 0.9; Schallschutzklasse: 32; Sonnenschutztyp: Movable
Fensteröffnung | H2 Ebene +3 | 1255Fen0811529580 | m² | 0 | Fensterarbeiten | Fensteröffnung | 0 | 11.25 | NEW | 1205Wa 0000102054 | 0 | - | 0,51 | AllplanAttributes - ash D_Detailverweis: <undefiniert>; U-Wert: 0.9; Schallschutzklasse: 32; Sonnenschutztyp: Movable
Fensteröffnung | H2 Ebene +3 | 1255Fen0811529578 | m² | 0 | Fensterarbeiten | Fensteröffnung | 0 | 11.25 | NEW | 1205Wa 0000102051 | 0 | - | 0,51 | AllplanAttributes - ash D_Detailverweis: <undefiniert>; U-Wert: 0.9; Schallschutzklasse: 32; Sonnenschutztyp: Movable
2 x Fensteröffnung | H2 Ebene +3 | 1255Fen0811528246 | m² | 0 | Wärmedämm-Verbundsysteme | Fensteröffnung | 0 | 11.25 | NEW | 1205Wa 0000102005 | 0 | - | 0,51 | AllplanAttributes - Material: Fensterelement; Außenliegend: yes; ash D_Detailverweis: <undefiniert>; U-Wert: 0.9; Schallschutzklasse: 32; Sonnenschutztyp: Movable
Fensteröffnung | H2 Ebene +3 | 1255Fen0811528233 | m² |  | Wärmedämm-Verbundsysteme | Fensteröffnung |  | 11.25 | NEW | 1205Wa 0000101990 | 0 | - | 0,51 | AllplanAttributes - Material: Fensterelement; Tragendes Bauteil: no; Brandabschnittsdefinierendes Bauteil: no; ash D_Detailverweis: <undefiniert>; U-Wert: 0.9; Schallschutzklasse: 32; Sonnenschutztyp: Movable
Fensteröffnung | H2 Ebene +3 | 1255Fen0811529496 | m² |  | Wärmedämm-Verbundsysteme | Fensteröffnung |  | 11.25 | NEW | 1205Wa 0000101990 | 0 | - | 0,51 | AllplanAttributes - Material: Fensterelement; Tragendes Bauteil: no; Brandabschnittsdefinierendes Bauteil: no; ash D_Detailverweis: <undefiniert>; U-Wert: 0.9; Schallschutzklasse: 32; Sonnenschutztyp: Movable
2 x Fensteröffnung | H2 Ebene +3 | 1255Fen0811529509 | m² | 0 | Wärmedämm-Verbundsysteme | Fensteröffnung | 0 | 11.25 | NEW | 1205Wa 0000102005 | 0 | - | 0,51 | AllplanAttributes - Material: Fensterelement; Außenliegend: yes; ash D_Detailverweis: <undefiniert>; U-Wert: 0.9; Schallschutzklasse: 32; Sonnenschutztyp: Movable
2 x Fensteröffnung | H2 Ebene +3 | 1255Fen0811528244 | m³ | 0 | Wärmedämm-Verbundsysteme | Fensteröffnung | 0 | 11.25 | NEW | 1205Wa 0000102020 | 0 | - | 0,51 | AllplanAttributes - ash D_Detailverweis: <undefiniert>; U-Wert: 0.9; Schallschutzklasse: 32; Sonnenschutztyp: Movable
2 x Fensteröffnung | H2 Ebene +3 | 1255Fen0811529507 | m³ | 0 | Wärmedämm-Verbundsysteme | Fensteröffnung | 0 | 11.25 | NEW | 1205Wa 0000102020 | 0 | - | 0,51 | AllplanAttributes - ash D_Detailverweis: <undefiniert>; U-Wert: 0.9; Schallschutzklasse: 32; Sonnenschutztyp: Movable
2 x Fensteröffnung | H2 Ebene +3 | 1255Fen0811528242 | m³ | 0 | Wärmedämm-Verbundsysteme | Fensteröffnung | 0 | 11.25 | NEW | 1205Wa 0000102017 | 0 | - | 0,51 | AllplanAttributes - ash D_Detailverweis: <undefiniert>; U-Wert: 0.9; Schallschutzklasse: 32; Sonnenschutztyp: Movable
2 x Fensteröffnung | H2 Ebene +3 | 1255Fen0811529505 | m³ | 0 | Wärmedämm-Verbundsysteme | Fensteröffnung | 0 | 11.25 | NEW | 1205Wa 0000102017 | 0 | - | 0,51 | AllplanAttributes - ash D_Detailverweis: <undefiniert>; U-Wert: 0.9; Schallschutzklasse: 32; Sonnenschutztyp: Movable
2 x Fensteröffnung | H2 Ebene +3 | 1255Fen0811528240 | m² | 0 | Wärmedämm-Verbundsysteme | Fensteröffnung | 0 | 11.25 | NEW | 1205Wa 0000102014 | 0 | - | 0,51 | AllplanAttributes - ash D_Detailverweis: <undefiniert>; U-Wert: 0.9; Schallschutzklasse: 32; Sonnenschutztyp: Movable
2 x Fensteröffnung | H2 Ebene +3 | 1255Fen0811529503 | m² | 0 | Wärmedämm-Verbundsysteme | Fensteröffnung | 0 | 11.25 | NEW | 1205Wa 0000102014 | 0 | - | 0,51 | AllplanAttributes - ash D_Detailverweis: <undefiniert>; U-Wert: 0.9; Schallschutzklasse: 32; Sonnenschutztyp: Movable
2 x Fensteröffnung | H2 Ebene +3 | 1255Fen0811528238 | m² | 0 | Wärmedämm-Verbundsysteme | Fensteröffnung | 0 | 11.25 | NEW | 1205Wa 0000102011 | 0 | - | 0,51 | AllplanAttributes - ash D_Detailverweis: <undefiniert>; U-Wert: 0.9; Schallschutzklasse: 32; Sonnenschutztyp: Movable
2 x Fensteröffnung | H2 Ebene +3 | 1255Fen0811529501 | m² | 0 | Wärmedämm-Verbundsysteme | Fensteröffnung | 0 | 11.25 | NEW | 1205Wa 0000102011 | 0 | - | 0,51 | AllplanAttributes - ash D_Detailverweis: <undefiniert>; U-Wert: 0.9; Schallschutzklasse: 32; Sonnenschutztyp: Movable
2 x Fensteröffnung | H2 Ebene +3 | 1255Fen0811528236 | m² | 0 | Wärmedämm-Verbundsysteme | Fensteröffnung | 0 | 11.25 | NEW | 1205Wa 0000102008 | 0 | - | 0,51 | AllplanAttributes - ash D_Detailverweis: <undefiniert>; U-Wert: 0.9; Schallschutzklasse: 32; Sonnenschutztyp: Movable
2 x Fensteröffnung | H2 Ebene +3 | 1255Fen0811529499 | m² | 0 | Wärmedämm-Verbundsysteme | Fensteröffnung | 0 | 11.25 | NEW | 1205Wa 0000102008 | 0 | - | 0,51 | AllplanAttributes - ash D_Detailverweis: <undefiniert>; U-Wert: 0.9; Schallschutzklasse: 32; Sonnenschutztyp: Movable
Fensteröffnung | H2 Ebene +3 | 1255Fen0811529473 | m² |  | Betonarbeiten | Fensteröffnung |  | 11.25 | NEW | 1205Wa 0000102227 | 0 | - | 0,51 | AllplanAttributes - ash D_Detailverweis: <undefiniert>; U-Wert: 0.9; Schallschutzklasse: 32; Sonnenschutztyp: Movable
Fensteröffnung | H2 Ebene +3 | 1255Fen0811529415 | m² |  | Fensterarbeiten | Fensteröffnung |  | 11.25 |  | 1205Wa 0000102227 | 0 | - | 0,51 | AllplanAttributes - ash D_Detailverweis: <undefiniert>; U-Wert: 0.9; Schallschutzklasse: 32; Sonnenschutztyp: Movable
Fensteröffnung | H2 Ebene +3 | 1255Fen0811528150 | m² |  | Fensterarbeiten | Fensteröffnung |  | 11.25 |  | 1205Wa 0000102227 | 0 | - | 0,51 | AllplanAttributes - ash D_Detailverweis: <undefiniert>; U-Wert: 0.9; Schallschutzklasse: 32; Sonnenschutztyp: Movable
Fensteröffnung | H2 Ebene +3 | 1255Fen0811528209 | m² |  | Betonarbeiten | Fensteröffnung |  | 11.25 | NEW | 1205Wa 0000102227 | 0 | - | 0,51 | AllplanAttributes - ash D_Detailverweis: <undefiniert>; U-Wert: 0.9; Schallschutzklasse: 32; Sonnenschutztyp: Movable
Fensteröffnung | H2 Ebene +3 | 1255Fen0811529484 | m³ | 0 | Betonarbeiten | Fensteröffnung | 0 | 11.25 | NEW | 1205Wa 0000102231 | 0 | - | 0,51 | AllplanAttributes - Material: Fensterelement; ash D_Detailverweis: <undefiniert>; U-Wert: 0.9; Schallschutzklasse: 32; Sonnenschutztyp: Movable
Fensteröffnung | H2 Ebene +3 | 1255Fen0811529428 | m³ | 0 | Fensterarbeiten | Fensteröffnung | 0 | 11.25 |  | 1205Wa 0000102231 | 0 | - | 0,51 | AllplanAttributes - ash D_Detailverweis: <undefiniert>; U-Wert: 0.9; Schallschutzklasse: 32; Sonnenschutztyp: Movable
Fensteröffnung | H2 Ebene +3 | 1255Fen0811528163 | m³ | 0 | Fensterarbeiten | Fensteröffnung | 0 | 11.25 |  | 1205Wa 0000102231 | 0 | - | 0,51 | AllplanAttributes - ash D_Detailverweis: <undefiniert>; U-Wert: 0.9; Schallschutzklasse: 32; Sonnenschutztyp: Movable
Fensteröffnung | H2 Ebene +3 | 1255Fen0811528220 | m³ | 0 | Betonarbeiten | Fensteröffnung | 0 | 11.25 | NEW | 1205Wa 0000102231 | 0 | - | 0,51 | AllplanAttributes - Material: Fensterelement; ash D_Detailverweis: <undefiniert>; U-Wert: 0.9; Schallschutzklasse: 32; Sonnenschutztyp: Movable
Fensteröffnung | H2 Ebene +3 | 1255Fen0811529482 | m³ | 0 | Betonarbeiten | Fensteröffnung | 0 | 11.25 | NEW | 1205Wa 0000102235 | 0 | - | 0,51 | AllplanAttributes - ash D_Detailverweis: <undefiniert>; U-Wert: 0.9; Schallschutzklasse: 32; Sonnenschutztyp: Movable
Fensteröffnung | H2 Ebene +3 | 1255Fen0811529426 | m³ | 0 | Fensterarbeiten | Fensteröffnung | 0 | 11.25 |  | 1205Wa 0000102235 | 0 | - | 0,51 | AllplanAttributes - ash D_Detailverweis: <undefiniert>; U-Wert: 0.9; Schallschutzklasse: 32; Sonnenschutztyp: Movable
Fensteröffnung | H2 Ebene +3 | 1255Fen0811528161 | m³ | 0 | Fensterarbeiten | Fensteröffnung | 0 | 11.25 |  | 1205Wa 0000102235 | 0 | - | 0,51 | AllplanAttributes - ash D_Detailverweis: <undefiniert>; U-Wert: 0.9; Schallschutzklasse: 32; Sonnenschutztyp: Movable
Fensteröffnung | H2 Ebene +3 | 1255Fen0811528218 | m³ | 0 | Betonarbeiten | Fensteröffnung | 0 | 11.25 | NEW | 1205Wa 0000102235 | 0 | - | 0,51 | AllplanAttributes - ash D_Detailverweis: <undefiniert>; U-Wert: 0.9; Schallschutzklasse: 32; Sonnenschutztyp: Movable
Fensteröffnung | H2 Ebene +3 | 1255Fen0811529480 | m² | 0 | Betonarbeiten | Fensteröffnung | 0 | 11.25 | NEW | 1205Wa 0000102239 | 0 | - | 0,51 | AllplanAttributes - ash D_Detailverweis: <undefiniert>; U-Wert: 0.9; Schallschutzklasse: 32; Sonnenschutztyp: Movable
Fensteröffnung | H2 Ebene +3 | 1255Fen0811529424 | m² | 0 | Fensterarbeiten | Fensteröffnung | 0 | 11.25 |  | 1205Wa 0000102239 | 0 | - | 0,51 | AllplanAttributes - ash D_Detailverweis: <undefiniert>; U-Wert: 0.9; Schallschutzklasse: 32; Sonnenschutztyp: Movable
Fensteröffnung | H2 Ebene +3 | 1255Fen0811528159 | m² | 0 | Fensterarbeiten | Fensteröffnung | 0 | 11.25 |  | 1205Wa 0000102239 | 0 | - | 0,51 | AllplanAttributes - ash D_Detailverweis: <undefiniert>; U-Wert: 0.9; Schallschutzklasse: 32; Sonnenschutztyp: Movable
Fensteröffnung | H2 Ebene +3 | 1255Fen0811528216 | m² | 0 | Betonarbeiten | Fensteröffnung | 0 | 11.25 | NEW | 1205Wa 0000102239 | 0 | - | 0,51 | AllplanAttributes - ash D_Detailverweis: <undefiniert>; U-Wert: 0.9; Schallschutzklasse: 32; Sonnenschutztyp: Movable
Fensteröffnung | H2 Ebene +3 | 1255Fen0811529478 | m² | 0 | Betonarbeiten | Fensteröffnung | 0 | 11.25 | NEW | 1205Wa 0000102243 | 0 | - | 0,51 | AllplanAttributes - ash D_Detailverweis: <undefiniert>; U-Wert: 0.9; Schallschutzklasse: 32; Sonnenschutztyp: Movable
Fensteröffnung | H2 Ebene +3 | 1255Fen0811529422 | m² | 0 | Fensterarbeiten | Fensteröffnung | 0 | 11.25 | NEW | 1205Wa 0000102243 | 0 | - | 0,51 | AllplanAttributes - ash D_Detailverweis: <undefiniert>; U-Wert: 0.9; Schallschutzklasse: 32; Sonnenschutztyp: Movable
Fensteröffnung | H2 Ebene +3 | 1255Fen0811528157 | m² | 0 | Fensterarbeiten | Fensteröffnung | 0 | 11.25 | NEW | 1205Wa 0000102243 | 0 | - | 0,51 | AllplanAttributes - ash D_Detailverweis: <undefiniert>; U-Wert: 0.9; Schallschutzklasse: 32; Sonnenschutztyp: Movable
Fensteröffnung | H2 Ebene +3 | 1255Fen0811528214 | m² | 0 | Betonarbeiten | Fensteröffnung | 0 | 11.25 | NEW | 1205Wa 0000102243 | 0 | - | 0,51 | AllplanAttributes - ash D_Detailverweis: <undefiniert>; U-Wert: 0.9; Schallschutzklasse: 32; Sonnenschutztyp: Movable
Fensteröffnung | H2 Ebene +3 | 1255Fen0811529476 | m² | 0 | Betonarbeiten | Fensteröffnung | 0 | 11.25 | NEW | 1205Wa 0000102247 | 0 | - | 0,51 | AllplanAttributes - ash D_Detailverweis: <undefiniert>; U-Wert: 0.9; Schallschutzklasse: 32; Sonnenschutztyp: Movable
Fensteröffnung | H2 Ebene +3 | 1255Fen0811529420 | m² | 0 | Fensterarbeiten | Fensteröffnung | 0 | 11.25 | NEW | 1205Wa 0000102247 | 0 | - | 0,51 | AllplanAttributes - ash D_Detailverweis: <undefiniert>; U-Wert: 0.9; Schallschutzklasse: 32; Sonnenschutztyp: Movable
Fensteröffnung | H2 Ebene +3 | 1255Fen0811528155 | m² | 0 | Fensterarbeiten | Fensteröffnung | 0 | 11.25 | NEW | 1205Wa 0000102247 | 0 | - | 0,51 | AllplanAttributes - ash D_Detailverweis: <undefiniert>; U-Wert: 0.9; Schallschutzklasse: 32; Sonnenschutztyp: Movable
Fensteröffnung | H2 Ebene +3 | 1255Fen0811528212 | m² | 0 | Betonarbeiten | Fensteröffnung | 0 | 11.25 | NEW | 1205Wa 0000102247 | 0 | - | 0,51 | AllplanAttributes - ash D_Detailverweis: <undefiniert>; U-Wert: 0.9; Schallschutzklasse: 32; Sonnenschutztyp: Movable
Fensteröffnung | H2 Ebene +3 | 1255Fen0811529470 | m² | 0 | Betonarbeiten | Fensteröffnung | 0 | 11.25 | NEW | 1205Wa 0000102251 | 0 | - | 0,51 | AllplanAttributes - ash D_Detailverweis: FSE1; ash D_Plannummer: D786; U-Wert: 0.9; Schallschutzklasse: 32; Sonnenschutztyp: Movable
Fensteröffnung | H2 Ebene +3 | 1255Fen0811529418 | m² | 0 | Fensterarbeiten | Fensteröffnung | 0 | 11.25 | NEW | 1205Wa 0000102251 | 0 | - | 0,51 | AllplanAttributes - ash D_Detailverweis: <undefiniert>; U-Wert: 0.9; Schallschutzklasse: 32; Sonnenschutztyp: Movable
Fensteröffnung | H2 Ebene +3 | 1255Fen0811528153 | m² | 0 | Fensterarbeiten | Fensteröffnung | 0 | 11.25 | NEW | 1205Wa 0000102251 | 0 | - | 0,51 | AllplanAttributes - ash D_Detailverweis: <undefiniert>; U-Wert: 0.9; Schallschutzklasse: 32; Sonnenschutztyp: Movable
Fensteröffnung | H2 Ebene +3 | 1255Fen0811528206 | m² | 0 | Betonarbeiten | Fensteröffnung | 0 | 11.25 | NEW | 1205Wa 0000102251 | 0 | - | 0,51 | AllplanAttributes - ash D_Detailverweis: FSE1; ash D_Plannummer: D786; U-Wert: 0.9; Schallschutzklasse: 32; Sonnenschutztyp: Movable
Fensteröffnung | H2 Ebene +3 | 1255Fen0811529365 | m² |  | Fensterarbeiten | Fensteröffnung |  | 11.25 |  | 1205Wa 0000180852 | 0 | - | 0,51 | AllplanAttributes - ash D_Detailverweis: <undefiniert>; U-Wert: 0.9; Schallschutzklasse: 32; Sonnenschutztyp: Movable
Fensteröffnung | H2 Ebene +3 | 1255Fen0811529309 | m² |  | Fensterarbeiten | Fensteröffnung |  | 11.25 |  | 1205Wa 0000180852 | 0 | - | 0,51 | AllplanAttributes - ash D_Detailverweis: <undefiniert>; U-Wert: 0.9; Schallschutzklasse: 32; Sonnenschutztyp: Movable
2 x Fensteröffnung | H2 Ebene +3 | 1255Fen0811529378 | m³ | 0 | Fensterarbeiten | Fensteröffnung | 0 | 11.25 |  | 1205Wa 0000180851 | 0 | - | 0,51 | AllplanAttributes - ash D_Detailverweis: <undefiniert>; U-Wert: 0.9; Schallschutzklasse: 32; Sonnenschutztyp: Movable
2 x Fensteröffnung | H2 Ebene +3 | 1255Fen0811529322 | m³ | 0 | Fensterarbeiten | Fensteröffnung | 0 | 11.25 |  | 1205Wa 0000180851 | 0 | - | 0,51 | AllplanAttributes - ash D_Detailverweis: <undefiniert>; U-Wert: 0.9; Schallschutzklasse: 32; Sonnenschutztyp: Movable; Bezeichnung: Fensteröffnung
2 x Fensteröffnung | H2 Ebene +3 | 1255Fen0811529376 | m³ | 0 | Fensterarbeiten | Fensteröffnung | 0 | 11.25 |  | 1205Wa 0000180850 | 0 | - | 0,51 | AllplanAttributes - ash D_Detailverweis: <undefiniert>; U-Wert: 0.9; Schallschutzklasse: 32; Sonnenschutztyp: Movable
2 x Fensteröffnung | H2 Ebene +3 | 1255Fen0811529320 | m³ | 0 | Fensterarbeiten | Fensteröffnung | 0 | 11.25 |  | 1205Wa 0000180850 | 0 | - | 0,51 | AllplanAttributes - ash D_Detailverweis: <undefiniert>; U-Wert: 0.9; Schallschutzklasse: 32; Sonnenschutztyp: Movable
2 x Fensteröffnung | H2 Ebene +3 | 1255Fen0811529374 | m² | 0 | Fensterarbeiten | Fensteröffnung | 0 | 11.25 |  | 1205Wa 0000180849 | 0 | - | 0,51 | AllplanAttributes - ash D_Detailverweis: <undefiniert>; U-Wert: 0.9; Schallschutzklasse: 32; Sonnenschutztyp: Movable
2 x Fensteröffnung | H2 Ebene +3 | 1255Fen0811529318 | m² | 0 | Fensterarbeiten | Fensteröffnung | 0 | 11.25 |  | 1205Wa 0000180849 | 0 | - | 0,51 | AllplanAttributes - ash D_Detailverweis: <undefiniert>; U-Wert: 0.9; Schallschutzklasse: 32; Sonnenschutztyp: Movable
2 x Fensteröffnung | H2 Ebene +3 | 1255Fen0811529372 | m² | 0 | Fensterarbeiten | Fensteröffnung | 0 | 11.25 | NEW | 1205Wa 0000180848 | 0 | - | 0,51 | AllplanAttributes - ash D_Detailverweis: <undefiniert>; U-Wert: 0.9; Schallschutzklasse: 32; Sonnenschutztyp: Movable
2 x Fensteröffnung | H2 Ebene +3 | 1255Fen0811529316 | m² | 0 | Fensterarbeiten | Fensteröffnung | 0 | 11.25 | NEW | 1205Wa 0000180848 | 0 | - | 0,51 | AllplanAttributes - ash D_Detailverweis: <undefiniert>; U-Wert: 0.9; Schallschutzklasse: 32; Sonnenschutztyp: Movable
2 x Fensteröffnung | H2 Ebene +3 | 1255Fen0811529370 | m² | 0 | Fensterarbeiten | Fensteröffnung | 0 | 11.25 | NEW | 1205Wa 0000180847 | 0 | - | 0,51 | AllplanAttributes - ash D_Detailverweis: <undefiniert>; U-Wert: 0.9; Schallschutzklasse: 32; Sonnenschutztyp: Movable
2 x Fensteröffnung | H2 Ebene +3 | 1255Fen0811529314 | m² | 0 | Fensterarbeiten | Fensteröffnung | 0 | 11.25 | NEW | 1205Wa 0000180847 | 0 | - | 0,51 | AllplanAttributes - ash D_Detailverweis: <undefiniert>; U-Wert: 0.9; Schallschutzklasse: 32; Sonnenschutztyp: Movable
Fensteröffnung | H2 Ebene +3 | 1255Fen0811529368 | m² | 0 | Fensterarbeiten | Fensteröffnung | 0 | 11.25 | NEW | 1205Wa 0000180846 | 0 | - | 0,51 | AllplanAttributes - ash D_Detailverweis: <undefiniert>; U-Wert: 0.9; Schallschutzklasse: 32; Sonnenschutztyp: Movable
Fensteröffnung | H2 Ebene +3 | 1255Fen0811529312 | m² | 0 | Fensterarbeiten | Fensteröffnung | 0 | 11.25 | NEW | 1205Wa 0000180846 | 0 | - | 0,51 | AllplanAttributes - ash D_Detailverweis: <undefiniert>; U-Wert: 0.9; Schallschutzklasse: 32; Sonnenschutztyp: Movable
Fensteröffnung | H2 Ebene +3 | 1255Fen0000001755 | m² |  | Wärmedämm-Verbundsysteme | Fensteröffnung |  | 11.25 | NEW | 1255Wa 0000001928 | AllplanAttributes - Material: Fensterelement; Tragendes Bauteil: no; Brandabschnittsdefinierendes Bauteil: no
Fensteröffnung | H2 Ebene +3 | 1255Fen0000001757 | m³ | 0 | Wärmedämm-Verbundsysteme | Fensteröffnung | 0 | 11.25 | NEW | 1255Wa 0000001922 | AllplanAttributes - Material: Fensterelement; Außenliegend: yes
Fensteröffnung | H2 Ebene +3 | 1255Fen0000001759 | m³ | 0 | Wärmedämm-Verbundsysteme | Fensteröffnung | 0 | 11.25 | NEW | 1255Wa 0000001917
Fensteröffnung | H2 Ebene +3 | 1255Fen0000001761 | m² | 0 | Wärmedämm-Verbundsysteme | Fensteröffnung | 0 | 11.25 | NEW | 1255Wa 0000001912
Fensteröffnung | H2 Ebene +3 | 1255Fen0000001763 | m² | 0 | Wärmedämm-Verbundsysteme | Fensteröffnung | 0 | 11.25 | NEW | 1255Wa 0000001907
Fensteröffnung | H2 Ebene +3 | 1255Fen0000001765 | m² | 0 | Wärmedämm-Verbundsysteme | Fensteröffnung | 0 | 11.25 | NEW | 1255Wa 0000001902
Fensteröffnung | H2 Ebene +3 | 1255Fen0000001753 | m² | 0 | Wärmedämm-Verbundsysteme | Fensteröffnung | 0 | 11.25 | NEW | 1255Wa 0000001897
Fensteröffnung | H2 Ebene +3 | 1255Fen0000004836 | m² |  | Wärmedämm-Verbundsysteme | Fensteröffnung |  | 11.25 | NEW | 1255Wa 0000004744 | AllplanAttributes - Material: Fensterelement; Tragendes Bauteil: no; Brandabschnittsdefinierendes Bauteil: no
Fensteröffnung | H2 Ebene +3 | 1255Fen0000004828 | m² |  | Wärmedämm-Verbundsysteme | Fensteröffnung |  | 11.25 | NEW | 1255Wa 0000004744 | AllplanAttributes - Material: Fensterelement; Tragendes Bauteil: no; Brandabschnittsdefinierendes Bauteil: no
Fensteröffnung | H2 Ebene +3 | 1255Fen0000004536 | m³ | 0 | Wärmedämm-Verbundsysteme | Fensteröffnung | 0 | 11.25 | NEW | 1255Wa 0000004752 | AllplanAttributes - Material: Fensterelement; Außenliegend: yes
Fensteröffnung | H2 Ebene +3 | 1255Fen0000004512 | m³ | 0 | Wärmedämm-Verbundsysteme | Fensteröffnung | 0 | 11.25 | NEW | 1255Wa 0000004752 | AllplanAttributes - Material: Fensterelement; Außenliegend: yes
Fensteröffnung | H2 Ebene +3 | 1255Fen0000004538 | m³ | 0 | Wärmedämm-Verbundsysteme | Fensteröffnung | 0 | 11.25 | NEW | 1255Wa 0000004760
Fensteröffnung | H2 Ebene +3 | 1255Fen0000004514 | m³ | 0 | Wärmedämm-Verbundsysteme | Fensteröffnung | 0 | 11.25 | NEW | 1255Wa 0000004760
Fensteröffnung | H2 Ebene +3 | 1255Fen0000004540 | m² | 0 | Wärmedämm-Verbundsysteme | Fensteröffnung | 0 | 11.25 | NEW | 1255Wa 0000004768
Fensteröffnung | H2 Ebene +3 | 1255Fen0000004516 | m² | 0 | Wärmedämm-Verbundsysteme | Fensteröffnung | 0 | 11.25 | NEW | 1255Wa 0000004768
Fensteröffnung | H2 Ebene +3 | 1255Fen0000004542 | m² | 0 | Wärmedämm-Verbundsysteme | Fensteröffnung | 0 | 11.25 | NEW | 1255Wa 0000004776
Fensteröffnung | H2 Ebene +3 | 1255Fen0000004518 | m² | 0 | Wärmedämm-Verbundsysteme | Fensteröffnung | 0 | 11.25 | NEW | 1255Wa 0000004776
Fensteröffnung | H2 Ebene +3 | 1255Fen0000004544 | m² | 0 | Wärmedämm-Verbundsysteme | Fensteröffnung | 0 | 11.25 | NEW | 1255Wa 0000004784
Fensteröffnung | H2 Ebene +3 | 1255Fen0000004520 | m² | 0 | Wärmedämm-Verbundsysteme | Fensteröffnung | 0 | 11.25 | NEW | 1255Wa 0000004784
Fensteröffnung | H2 Ebene +3 | 1255Fen0000004546 | m² | 0 | Wärmedämm-Verbundsysteme | Fensteröffnung | 0 | 11.25 | NEW | 1255Wa 0000004792
Fensteröffnung | H2 Ebene +3 | 1255Fen0000004522 | m² | 0 | Wärmedämm-Verbundsysteme | Fensteröffnung | 0 | 11.25 | NEW | 1255Wa 0000004792
Fensteröffnung | H2 Ebene +3 | 1255Fen0000002343 | m² |  | Wärmedämm-Verbundsysteme | Fensteröffnung |  | 11.25 | NEW | 1255Wa 0000002160 | AllplanAttributes - Material: Fensterelement; Tragendes Bauteil: no; Brandabschnittsdefinierendes Bauteil: no
Fensteröffnung | H2 Ebene +3 | 1255Fen0000002333 | m² |  | Wärmedämm-Verbundsysteme | Fensteröffnung |  | 11.25 | NEW | 1255Wa 0000002160 | AllplanAttributes - Material: Fensterelement; Tragendes Bauteil: no; Brandabschnittsdefinierendes Bauteil: no
Fensteröffnung | H2 Ebene +3 | 1255Fen0000002056 | m³ | 0 | Wärmedämm-Verbundsysteme | Fensteröffnung | 0 | 11.25 | NEW | 1255Wa 0000002168 | AllplanAttributes - Material: Fensterelement; Außenliegend: yes
Fensteröffnung | H2 Ebene +3 | 1255Fen0000002040 | m³ | 0 | Wärmedämm-Verbundsysteme | Fensteröffnung | 0 | 11.25 | NEW | 1255Wa 0000002168 | AllplanAttributes - Material: Fensterelement; Außenliegend: yes
Fensteröffnung | H2 Ebene +3 | 1255Fen0000002058 | m³ | 0 | Wärmedämm-Verbundsysteme | Fensteröffnung | 0 | 11.25 | NEW | 1255Wa 0000002176
Fensteröffnung | H2 Ebene +3 | 1255Fen0000002038 | m³ | 0 | Wärmedämm-Verbundsysteme | Fensteröffnung | 0 | 11.25 | NEW | 1255Wa 0000002176
Fensteröffnung | H2 Ebene +3 | 1255Fen0000002060 | m² | 0 | Wärmedämm-Verbundsysteme | Fensteröffnung | 0 | 11.25 | NEW | 1255Wa 0000002184
Fensteröffnung | H2 Ebene +3 | 1255Fen0000002036 | m² | 0 | Wärmedämm-Verbundsysteme | Fensteröffnung | 0 | 11.25 | NEW | 1255Wa 0000002184
Fensteröffnung | H2 Ebene +3 | 1255Fen0000002062 | m² | 0 | Wärmedämm-Verbundsysteme | Fensteröffnung | 0 | 11.25 | NEW | 1255Wa 0000002192
Fensteröffnung | H2 Ebene +3 | 1255Fen0000002034 | m² | 0 | Wärmedämm-Verbundsysteme | Fensteröffnung | 0 | 11.25 | NEW | 1255Wa 0000002192
Fensteröffnung | H2 Ebene +3 | 1255Fen0000002064 | m² | 0 | Wärmedämm-Verbundsysteme | Fensteröffnung | 0 | 11.25 | NEW | 1255Wa 0000002200
Fensteröffnung | H2 Ebene +3 | 1255Fen0000002032 | m² | 0 | Wärmedämm-Verbundsysteme | Fensteröffnung | 0 | 11.25 | NEW | 1255Wa 0000002200
Fensteröffnung | H2 Ebene +3 | 1255Fen0000002066 | m² | 0 | Wärmedämm-Verbundsysteme | Fensteröffnung | 0 | 11.25 | NEW | 1255Wa 0000002208
Fensteröffnung | H2 Ebene +3 | 1255Fen0000002042 | m² | 0 | Wärmedämm-Verbundsysteme | Fensteröffnung | 0 | 11.25 | NEW | 1255Wa 0000002208
Fensteröffnung | H2 Ebene +3 | 1255Fen0811537279 | m² |  | Wärmedämm-Verbundsysteme | Fensteröffnung |  | 11.25 | NEW | 1255Wa 0000001668 | 0 | AllplanAttributes - Material: Fensterelement; Tragendes Bauteil: no; Brandabschnittsdefinierendes Bauteil: no
Fensteröffnung | H2 Ebene +3 | 1255Fen0811537332 | m² |  | Wärmedämm-Verbundsysteme | Fensteröffnung |  | 11.25 | NEW | 1255Wa 0000001668 | 0 | AllplanAttributes - Material: Fensterelement; Tragendes Bauteil: no; Brandabschnittsdefinierendes Bauteil: no
Fensteröffnung | H2 Ebene +3 | 1255Fen0811537480 | m² |  | Wärmedämm-Verbundsysteme | Fensteröffnung |  | 11.25 | NEW | 1255Wa 0000001561 | AllplanAttributes - Material: Fensterelement; Tragendes Bauteil: no; Brandabschnittsdefinierendes Bauteil: no
Fensteröffnung | H2 Ebene +3 | 1255Fen0811537278 | m³ | 0 | Wärmedämm-Verbundsysteme | Fensteröffnung | 0 | 11.25 | NEW | 1255Wa 0000001664 | 0 | AllplanAttributes - Material: Fensterelement; Außenliegend: yes
Fensteröffnung | H2 Ebene +3 | 1255Fen0811537331 | m³ | 0 | Wärmedämm-Verbundsysteme | Fensteröffnung | 0 | 11.25 | NEW | 1255Wa 0000001664 | 0 | AllplanAttributes - Material: Fensterelement; Außenliegend: yes
Fensteröffnung | H2 Ebene +3 | 1255Fen0811537479 | m³ | 0 | Wärmedämm-Verbundsysteme | Fensteröffnung | 0 | 11.25 | NEW | 1255Wa 0000001492 | AllplanAttributes - Material: Fensterelement; Außenliegend: yes
Fensteröffnung | H2 Ebene +3 | 1255Fen0811537277 | m³ | 0 | Wärmedämm-Verbundsysteme | Fensteröffnung | 0 | 11.25 | NEW | 1255Wa 0000001660 | 0
Fensteröffnung | H2 Ebene +3 | 1255Fen0811537330 | m³ | 0 | Wärmedämm-Verbundsysteme | Fensteröffnung | 0 | 11.25 | NEW | 1255Wa 0000001660 | 0
Fensteröffnung | H2 Ebene +3 | 1255Fen0811537478 | m³ | 0 | Wärmedämm-Verbundsysteme | Fensteröffnung | 0 | 11.25 | NEW | 1255Wa 0000001496
Fensteröffnung | H2 Ebene +3 | 1255Fen0811537276 | m² | 0 | Wärmedämm-Verbundsysteme | Fensteröffnung | 0 | 11.25 | NEW | 1255Wa 0000001656 | 0
Fensteröffnung | H2 Ebene +3 | 1255Fen0811537329 | m² | 0 | Wärmedämm-Verbundsysteme | Fensteröffnung | 0 | 11.25 | NEW | 1255Wa 0000001656 | 0
Fensteröffnung | H2 Ebene +3 | 1255Fen0811537477 | m² | 0 | Wärmedämm-Verbundsysteme | Fensteröffnung | 0 | 11.25 | NEW | 1255Wa 0000001500
Fensteröffnung | H2 Ebene +3 | 1255Fen0811537275 | m² | 0 | Wärmedämm-Verbundsysteme | Fensteröffnung | 0 | 11.25 | NEW | 1255Wa 0000001652 | 0
Fensteröffnung | H2 Ebene +3 | 1255Fen0811537328 | m² | 0 | Wärmedämm-Verbundsysteme | Fensteröffnung | 0 | 11.25 | NEW | 1255Wa 0000001652 | 0
Fensteröffnung | H2 Ebene +3 | 1255Fen0811537476 | m² | 0 | Wärmedämm-Verbundsysteme | Fensteröffnung | 0 | 11.25 | NEW | 1255Wa 0000001504
Fensteröffnung | H2 Ebene +3 | 1255Fen0811537274 | m² | 0 | Wärmedämm-Verbundsysteme | Fensteröffnung | 0 | 11.25 | NEW | 1255Wa 0000001648 | 0
Fensteröffnung | H2 Ebene +3 | 1255Fen0811537327 | m² | 0 | Wärmedämm-Verbundsysteme | Fensteröffnung | 0 | 11.25 | NEW | 1255Wa 0000001648 | 0
Fensteröffnung | H2 Ebene +3 | 1255Fen0811537475 | m² | 0 | Wärmedämm-Verbundsysteme | Fensteröffnung | 0 | 11.25 | NEW | 1255Wa 0000001508
Fensteröffnung | H2 Ebene +3 | 1255Fen0811537273 | m² | 0 | Wärmedämm-Verbundsysteme | Fensteröffnung | 0 | 11.25 | NEW | 1255Wa 0000001644 | 0
Fensteröffnung | H2 Ebene +3 | 1255Fen0811537326 | m² | 0 | Wärmedämm-Verbundsysteme | Fensteröffnung | 0 | 11.25 | NEW | 1255Wa 0000001644 | 0
Fensteröffnung | H2 Ebene +3 | 1255Fen0811537474 | m² | 0 | Wärmedämm-Verbundsysteme | Fensteröffnung | 0 | 11.25 | NEW | 1255Wa 0000001488
Fensteröffnung | H2 Ebene +3 | 1255Fen0811497973 | m² |  | Metallbau-, Schlosserarbeiten | Fensteröffnung |  |  | NEW
Fensteröffnung | H2 Ebene +3 | 1255Fen0811497974 | m² | 0 | Metallbau-, Schlosserarbeiten | Fensteröffnung | 0 |  | NEW
Fensteröffnung | H2 Ebene +3 | 1255Fen0811498465 | m² |  | Metallbau-, Schlosserarbeiten | Fensteröffnung |  |  | NEW
Fensteröffnung | H2 Ebene +3 | 1255Fen0811498466 | m² | 0 | Metallbau-, Schlosserarbeiten | Fensteröffnung | 0 |  | NEW
Türöffnung | H2 Ebene +3 | 1263Tür0812772218 | m² | 0 | Trockenbauarbeiten | Türöffnung | 0 | 11.25 |  | 1263Wa 0812772221 | AllplanAttributes - Codetext: Codetext; Türanschlag: DIN L; Attributset-Objekt: OpeningElement; Pset_OpeningElementCommon - FireExit: no; Reference: Codetext
Türöffnung | H2 Ebene +3 | 1263Tür0812772208 | m² | 0 | Trockenbauarbeiten | Türöffnung | 0 | 11.25 |  | 1263Wa 0812772221 | AllplanAttributes - Codetext: Codetext; Türanschlag: DIN L; Attributset-Objekt: OpeningElement; Pset_OpeningElementCommon - FireExit: no; Reference: Codetext
Türöffnung | H2 Ebene +3 | 1263Tür0812772210 | m² |  | Trockenbauarbeiten | Türöffnung |  | 11.25 |  | 1263Wa 0812772221 | AllplanAttributes - Codetext: Codetext; Türanschlag: DIN L; Attributset-Objekt: OpeningElement; Pset_OpeningElementCommon - FireExit: no; Reference: Codetext
Türöffnung | H2 Ebene +3 | 1263Tür0812772211 | m² |  | Trockenbauarbeiten | Türöffnung |  | 11.25 |  | 1263Wa 0812772221 | AllplanAttributes - Codetext: Codetext; Türanschlag: DIN L; Attributset-Objekt: OpeningElement; Pset_OpeningElementCommon - FireExit: no; Reference: Codetext
Türöffnung | H2 Ebene +3 | 1263Tür0812772209 | m² | 0 | Trockenbauarbeiten | Türöffnung | 0 | 11.25 |  | 1263Wa 0812772221 | AllplanAttributes - Codetext: Codetext; Türanschlag: DIN L; Attributset-Objekt: OpeningElement; Pset_OpeningElementCommon - FireExit: no; Reference: Codetext
Türöffnung | H2 Ebene +3 | 1263Tür0812772076 | m² | 0 | Trockenbauarbeiten | Türöffnung | 0 | 11.25 |  | 1263Wa 0812769623 | AllplanAttributes - Codetext: Codetext; Türanschlag: DIN R; Attributset-Objekt: OpeningElement; Pset_OpeningElementCommon - FireExit: no; Reference: Codetext
Türöffnung | H2 Ebene +3 | 1263Tür0812772065 | m² | 0 | Trockenbauarbeiten | Türöffnung | 0 | 11.25 |  | 1263Wa 0812769623 | AllplanAttributes - Codetext: Codetext; Türanschlag: DIN R; Attributset-Objekt: OpeningElement; Pset_OpeningElementCommon - FireExit: no; Reference: Codetext
Türöffnung | H2 Ebene +3 | 1263Tür0812771673 | m² |  | Trockenbauarbeiten | Türöffnung |  | 11.25 |  | 1263Wa 0812769623 | AllplanAttributes - Codetext: Codetext; Türanschlag: DIN R; Attributset-Objekt: OpeningElement; Pset_OpeningElementCommon - FireExit: no; Reference: Codetext
Türöffnung | H2 Ebene +3 | 1263Tür0812772054 | m² | 0 | Trockenbauarbeiten | Türöffnung | 0 | 11.25 |  | 1263Wa 0812769623 | AllplanAttributes - Codetext: Codetext; Türanschlag: DIN R; Attributset-Objekt: OpeningElement; Pset_OpeningElementCommon - FireExit: no; Reference: Codetext
Türöffnung | H2 Ebene +3 | 1263Tür0812772044 | m² |  | Trockenbauarbeiten | Türöffnung |  | 11.25 |  | 1263Wa 0812769623 | AllplanAttributes - Codetext: Codetext; Türanschlag: DIN R; Attributset-Objekt: OpeningElement; Pset_OpeningElementCommon - FireExit: no; Reference: Codetext
Türöffnung | H2 Ebene +3 | 1263Tür0812939716 | m² |  | Trockenbauarbeiten | Türöffnung |  | 11.25 | NEW | 1263Wa 0812547457 | AllplanAttributes - Türanschlag: -
Türöffnung | H2 Ebene +3 | 1263Tür0812546823 | m² |  | Trockenbauarbeiten | Türöffnung |  | 11.25 | NEW | 1263Wa 0812546848 | AllplanAttributes - Codetext: Codetext; Türanschlag: DIN L; Attributset-Objekt: OpeningElement; Pset_OpeningElementCommon - FireExit: no; Reference: Codetext
Türöffnung | H2 Ebene +3 | 1263Tür0812546496 | m² |  | Trockenbauarbeiten | Türöffnung |  | 11.25 |  | 1263Wa 0812546968 | AllplanAttributes - Codetext: Codetext; Türanschlag: DIN R; Attributset-Objekt: OpeningElement; Pset_OpeningElementCommon - FireExit: no; Reference: Codetext
Türöffnung | H2 Ebene +3 | 1263Tür0812996348 | m² |  | Trockenbauarbeiten | Türöffnung |  | 11.25 | NEW | 1263Wa 0812547457 | AllplanAttributes - Türanschlag: -
Türöffnung | H2 Ebene +3 | 1263Tür0812547369 | m² |  | Trockenbauarbeiten | Türöffnung |  | 11.25 |  | 1263Wa 0812547473 | AllplanAttributes - Türanschlag: DIN L
Türöffnung | H2 Ebene +3 | 1263Tür0812546682 | m² |  | Trockenbauarbeiten | Türöffnung |  | 11.25 | NEW | 1263Wa 0812546695 | AllplanAttributes - Türanschlag: -
Türöffnung | H2 Ebene +3 | 1263Tür0812976165 | m² |  | Trockenbauarbeiten | Türöffnung |  | 11.25 |  | 1263Wa 0812546950 | AllplanAttributes - Codetext: Codetext; Türanschlag: -; Attributset-Objekt: OpeningElement; Pset_OpeningElementCommon - FireExit: no; Reference: Codetext
SMT | H2 Ebene +3 | 1263Tür0812546462 | m² |  | Trockenbauarbeiten | Wand |  | 11.25 | NEW | 1263Wa 0812546978 | EI 60-A1 - A2,s1-d0 | AllplanAttributes - Material: WI-LB; Tragendes Bauteil: no; Brandabschnittsdefinierendes Bauteil: no; Außenliegend: no; U-Wert: 0; Schallschutzklasse: 0; Codetext: Codetext; Türanschlag: DIN L; 2D Interaktion: yes; Positionsnummer: 1; V6: 0 m; V7: 0 m; V8: 0 m; V9: 0; Glasanteil_berücksichtigen: 100; Typ: 0; Abstand_Öffn_Unten: 0.1 m; Brennbares Material: no; Brandverhalten: 0; Rauchschutz: no; Selbstschließend: no; Brandschutzklasse: A; ash T_Unterschnitt: -; ash T_Zulage Schachttür: no; ash T_Dichtschließend: yes; ash T_Zarge_Typ: U; ash T_Erforderl. Durchgangsbreite: 0 m; ash T_Türblatt sichtbar 2D: ja; ash T_Feststellanlage (FSA): -; ash T_nicht abschließbar: no; ash T_Tür-Nr.: Flurtür; ash T_Blatt_Oberfläche: -; ash T_Erford. Durgangshöhe: 0 m; ash T_Blatt_Material: -; ash T_Schallschutz: -; ash T_Zarge_Material: S; ash T_Raum zugehörigkeit: BS; W_Deckenanschluss: Gleitender Deckenanschluss Fall 01; Pset_OpeningElementCommon - FireExit: no; Reference: Codetext
Türöffnung | H2 Ebene +3 | 1263Tür0812768047 | m² |  | Metallbau-, Schlosserarbeiten | Türmakro |  | 11.25 | NEW | 1263Wa 0812546954 | AllplanAttributes - Material: TI-2F-AG-D-O; Tragendes Bauteil: yes; Brandabschnittsdefinierendes Bauteil: no; Codetext: Codetext; Türanschlag: DIN L; Attributset-Objekt: Door; Positionsnummer: 1; V6: 0 m; V7: 0 m; V8: 0 m; V9: 0; Glasanteil_berücksichtigen: 100; Typ: 0; Abstand_Öffn_Unten: 0.15 m; Brennbares Material: no; Brandverhalten: 0; Brandschutzklasse: A; ash T_Zulage Schachttür: no; ash T_Dichtschließend: no; ash T_Zarge_Typ: -; ash T_Erforderl. Durchgangsbreite: 0 m; ash T_Türblatt sichtbar 2D: ja; ash T_Feststellanlage (FSA): -; ash T_nicht abschließbar: no; ash T_Tür-Nr.: Technik H1; ash T_Blatt_Oberfläche: -; ash T_Erford. Durgangshöhe: 0 m; ash T_Blatt_Material: -; ash T_Schallschutz: -; ash T_Zarge_Material: -; ash T_Raum zugehörigkeit: BS; Pset_OpeningElementCommon - FireExit: no; Reference: Codetext; DoorCommon - Außenliegend: no; Feuerwiderstandsklasse: EI2 30; U-Wert: 0; Schallschutzklasse: 0; Rauchschutz: yes; Selbstschließend: yes
SMT | H2 Ebene +3 | 1263Tür0812546892 | m² |  | Metallbau-, Schlosserarbeiten | Türmakro |  | 11.25 | NEW | 1263Wa 0812546950 | AllplanAttributes - Material: TI-2F-AG-D-O; Tragendes Bauteil: yes; Brandabschnittsdefinierendes Bauteil: no; Codetext: Codetext; Türanschlag: DIN R; Attributset-Objekt: Door; Positionsnummer: 1; V6: 0 m; V7: 0 m; V8: 0 m; V9: 0; Glasanteil_berücksichtigen: 100; Typ: 0; Abstand_Öffn_Unten: 0.15 m; Brennbares Material: no; Brandverhalten: 0; Brandschutzklasse: A; ash T_Zulage Schachttür: no; ash T_Dichtschließend: no; ash T_Zarge_Typ: -; ash T_Erforderl. Durchgangsbreite: 0 m; ash T_Türblatt sichtbar 2D: ja; ash T_Feststellanlage (FSA): -; ash T_nicht abschließbar: no; ash T_Tür-Nr.: Technik H1; ash T_Blatt_Oberfläche: -; ash T_Erford. Durgangshöhe: 0 m; ash T_Blatt_Material: -; ash T_Schallschutz: -; ash T_Zarge_Material: -; ash T_Raum zugehörigkeit: BS; Pset_OpeningElementCommon - FireExit: no; Reference: Codetext; DoorCommon - Außenliegend: no; Feuerwiderstandsklasse: EI2 30; U-Wert: 0; Schallschutzklasse: 0; Rauchschutz: yes; Selbstschließend: yes
SMT | H2 Ebene +3 | 1263Tür0812546510 | m² |  | Metallbau-, Schlosserarbeiten | Türmakro |  | 11.25 | NEW | 1263Wa 0812546950 | AllplanAttributes - Material: TI-2F-AG-D-O; Tragendes Bauteil: yes; Brandabschnittsdefinierendes Bauteil: no; Codetext: Codetext; Türanschlag: DIN L; Attributset-Objekt: Door; Positionsnummer: 1; V6: 0 m; V7: 0 m; V8: 0 m; V9: 0; Glasanteil_berücksichtigen: 100; Typ: 0; Abstand_Öffn_Unten: 0.15 m; Brennbares Material: no; Brandverhalten: 0; Brandschutzklasse: A; ash T_Zulage Schachttür: no; ash T_Dichtschließend: no; ash T_Zarge_Typ: -; ash T_Erforderl. Durchgangsbreite: 0 m; ash T_Türblatt sichtbar 2D: ja; ash T_Feststellanlage (FSA): -; ash T_nicht abschließbar: no; ash T_Tür-Nr.: Technik H1; ash T_Blatt_Oberfläche: -; ash T_Erford. Durgangshöhe: 0 m; ash T_Blatt_Material: -; ash T_Schallschutz: -; ash T_Zarge_Material: -; ash T_Raum zugehörigkeit: BS; Pset_OpeningElementCommon - FireExit: no; Reference: Codetext; DoorCommon - Außenliegend: no; Feuerwiderstandsklasse: EI2 30; U-Wert: 0; Schallschutzklasse: 0; Rauchschutz: yes; Selbstschließend: yes
Türöffnung | H2 Ebene +3 | 1263Tür0812598124 | m² |  | Metallbau-, Schlosserarbeiten | Türmakro |  | 11.25 | NEW | 1263Wa 0812546503 | AllplanAttributes - Material: TI-2F-AG-D-O; Türanschlag: DIN L; Attributset-Objekt: Door; Positionsnummer: 1; V6: 0 m; V7: 0 m; V8: 0 m; V9: 0; Glasanteil_berücksichtigen: 100; ash T_Zulage Schachttür: no; ash T_Dichtschließend: no; ash T_Zarge_Typ: -; ash T_Erforderl. Durchgangsbreite: 0 m; ash T_Türblatt sichtbar 2D: ja; ash T_nicht abschließbar: no; ash T_Blatt_Oberfläche: -; ash T_Erford. Durgangshöhe: 0 m; ash T_Blatt_Material: -; ash T_Schallschutz: -; ash T_Zarge_Material: -; ash T_Raum zugehörigkeit: BS; DoorCommon - Außenliegend: no; Feuerwiderstandsklasse: EI2 30; U-Wert: 0; Rauchschutz: yes; Selbstschließend: yes
SMT | H2 Ebene +3 | 1263Tür0812915382 | m² |  | Metallbau-, Schlosserarbeiten | Türmakro |  | 11.25 | NEW | 1263Wa 0812915391 | AllplanAttributes - Material: TI-2F-AG-D-O; Türanschlag: DIN R; Attributset-Objekt: Door; Positionsnummer: 1; V6: 0 m; V7: 0 m; V8: 0 m; V9: 0; Glasanteil_berücksichtigen: 100; ash T_Zulage Schachttür: no; ash T_Dichtschließend: no; ash T_Zarge_Typ: -; ash T_Erforderl. Durchgangsbreite: 0 m; ash T_Türblatt sichtbar 2D: ja; ash T_nicht abschließbar: no; ash T_Blatt_Oberfläche: -; ash T_Erford. Durgangshöhe: 0 m; ash T_Blatt_Material: -; ash T_Schallschutz: -; ash T_Zarge_Material: -; ash T_Raum zugehörigkeit: BS; DoorCommon - Außenliegend: no; Feuerwiderstandsklasse: EI2 30; U-Wert: 0; Rauchschutz: yes; Selbstschließend: yes
Türöffnung | H2 Ebene +3 | 1263Tür0812768175 | m² |  | Trockenbauarbeiten | Türöffnung |  | 11.25 | NEW | 1263Wa 0812546807 | AllplanAttributes - Codetext: Codetext; Türanschlag: DIN R; Attributset-Objekt: OpeningElement; Pset_OpeningElementCommon - FireExit: no; Reference: Codetext
Türöffnung | H2 Ebene +3 | 1263Tür0812595860 | m² |  | Trockenbauarbeiten | Türöffnung |  | 11.25 |  | 1263Wa 0812595658 | AllplanAttributes - Codetext: Codetext; Türanschlag: DIN R; Attributset-Objekt: OpeningElement; Pset_OpeningElementCommon - FireExit: no; Reference: Codetext
Wandnische | H2 Ebene +3 | 1263Wni0812975003 | m² | 0 | Zimmer- und Holzbauarbeiten | Wandnische | 0 |  | NEW
Türöffnung | H2 Ebene +3 | 1263Tür0812546232 | m² |  | Trockenbauarbeiten | Türöffnung |  | 11.25 |  | 1263Wa 0812546811 | AllplanAttributes - Türanschlag: DIN L
Türöffnung | H2 Ebene +3 | 1263Tür0812795044 | m² | 0 | Trockenbauarbeiten | Türöffnung | 0 | 11.25 | NEW | 1263Wa 0812795009 | AllplanAttributes - Türanschlag: DIN L
Türöffnung | H2 Ebene +3 | 1263Tür0812609493 | m² |  | Trockenbauarbeiten | Türöffnung |  | 11.25 |  | 1263Wa 0812609602 | AllplanAttributes - Codetext: Codetext; Türanschlag: DIN L; Attributset-Objekt: OpeningElement; Pset_OpeningElementCommon - FireExit: no; Reference: Codetext
Türöffnung | H2 Ebene +3 | 1263Tür0812794388 | m² | 0 | Trockenbauarbeiten | Türöffnung | 0 | 11.25 | NEW | 1263Wa 0812794375 | AllplanAttributes - Türanschlag: DIN L
Türöffnung | H2 Ebene +3 | 1263Tür0812820185 | m² |  | Zimmer- und Holzbauarbeiten | Türöffnung |  | 11.25 |  | 1263Wa 0812546332 | AllplanAttributes - Codetext: Codetext; Türanschlag: DIN R; Attributset-Objekt: OpeningElement; Pset_OpeningElementCommon - FireExit: no; Reference: Codetext
Türöffnung | H2 Ebene +3 | 1263Tür0812995414 | m² |  | Zimmer- und Holzbauarbeiten | Türöffnung |  | 11.25 |  | 1263Wa 0812546332 | AllplanAttributes - Codetext: Codetext; Türanschlag: DIN R; Attributset-Objekt: OpeningElement; Pset_OpeningElementCommon - FireExit: no; Reference: Codetext
Türöffnung | H2 Ebene +3 | 1263Tür0812887447 | m² |  | Trockenbauarbeiten | Türöffnung |  | 11.25 | NEW | 1263Wa 0812546335 | AllplanAttributes - Türanschlag: -
Türöffnung | H2 Ebene +3 | 1263Tür0812735042 | m² |  | Trockenbauarbeiten | Türöffnung |  | 11.25 |  | 1263Wa 0812546912 | AllplanAttributes - Codetext: Codetext; Türanschlag: -; Attributset-Objekt: OpeningElement; Pset_OpeningElementCommon - FireExit: no; Reference: Codetext
Türöffnung | H2 Ebene +3 | 1263Tür0812768297 | m² |  | Trockenbauarbeiten | Türöffnung |  | 11.25 |  | 1263Wa 0812546912 | AllplanAttributes - Codetext: Codetext; Türanschlag: DIN L; Attributset-Objekt: OpeningElement; Pset_OpeningElementCommon - FireExit: no; Reference: Codetext
Türöffnung | H2 Ebene +3 | 1263Tür0812976459 | m² |  | Trockenbauarbeiten | Türöffnung |  | 11.25 |  | 1263Wa 0812546912 | AllplanAttributes - Codetext: Codetext; Türanschlag: DIN L; Attributset-Objekt: OpeningElement; Pset_OpeningElementCommon - FireExit: no; Reference: Codetext
SMT | H2 Ebene +3 | 1263Tür0812546381 | m² |  | Metallbau-, Schlosserarbeiten | Türmakro |  | 11.25 | NEW | 1263Wa 0812546898 | AllplanAttributes - Material: TI-1F-UZ-D; Codetext: Codetext; Türanschlag: DIN R; Attributset-Objekt: Door; Positionsnummer: 1; V6: 0 m; V7: 0 m; V8: 0 m; V9: 0; Glasanteil_berücksichtigen: 100; Abstand_Öffn_Unten: 0.15 m; ash T_Zulage Schachttür: no; ash T_Dichtschließend: no; ash T_Zarge_Typ: -; ash T_Erforderl. Durchgangsbreite: 0 m; ash T_Türblatt sichtbar 2D: ja; ash T_Feststellanlage (FSA): -; ash T_nicht abschließbar: no; ash T_Blatt_Oberfläche: -; ash T_Erford. Durgangshöhe: 0 m; ash T_Blatt_Material: -; ash T_Schallschutz: -; ash T_Zarge_Material: -; ash T_Raum zugehörigkeit: BS; Pset_OpeningElementCommon - FireExit: no; Reference: Codetext; DoorCommon - Außenliegend: no; Feuerwiderstandsklasse: EI2 30; U-Wert: 0; Rauchschutz: yes; Selbstschließend: yes
Türöffnung | H2 Ebene +3 | 1263Tür0812767675 | m² |  | Trockenbauarbeiten | Türöffnung |  | 11.25 |  | 1263Wa 0812546928 | AllplanAttributes - Codetext: Codetext; Türanschlag: DIN R; Attributset-Objekt: OpeningElement; Pset_OpeningElementCommon - FireExit: no; Reference: Codetext
Türöffnung | H2 Ebene +3 | 1263Tür0812819983 | m² |  | Zimmer- und Holzbauarbeiten | Türöffnung |  | 11.25 |  | 1263Wa 0812546930 | AllplanAttributes - Codetext: Codetext; Türanschlag: DIN L; Attributset-Objekt: OpeningElement; Pset_OpeningElementCommon - FireExit: no; Reference: Codetext
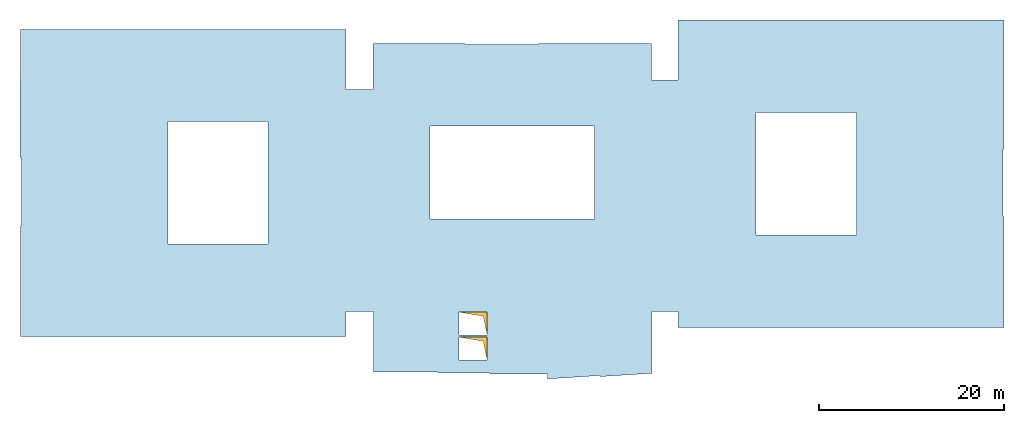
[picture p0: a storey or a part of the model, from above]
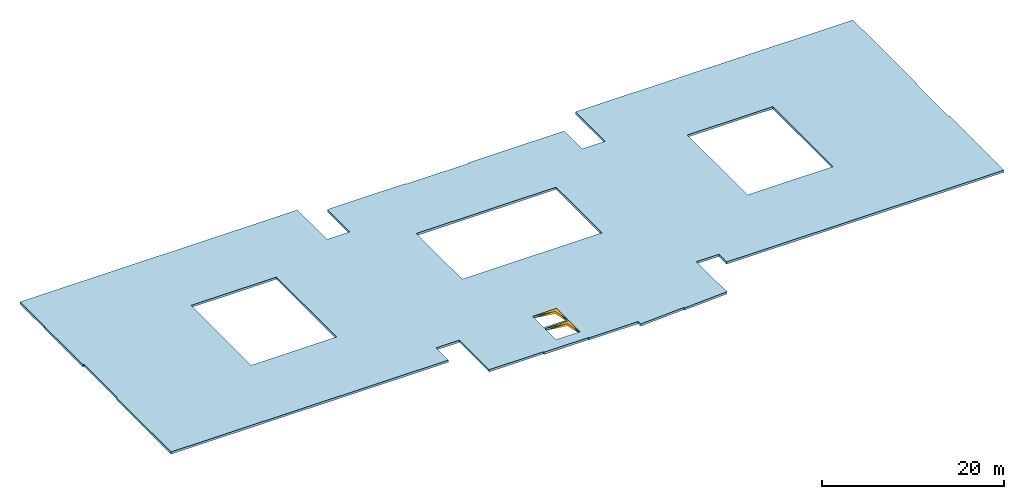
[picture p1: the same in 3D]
Properties of the parts of a building model (IFC4), part 30 of 80

# IfcOpeningElement: Opening (3497)
Name | In | Allright_Bauteil_ID | Abrechnungsart | Versatz_oben | Gewerk | Objektname | Versatz_unten | OKFF | Status | P_ID | AllplanAttributes, Feuerwiderstandsklasse | Sicherheitsklasse | g-Wert
Türöffnung | H2 Ebene +3 | 1263Tür0812605354 | m² |  | Trockenbauarbeiten | Türöffnung |  | 11.25 |  | 1263Wa 0812547457 | AllplanAttributes - Codetext: Codetext; Türanschlag: DIN R; Attributset-Objekt: OpeningElement; Pset_OpeningElementCommon - FireExit: no; Reference: Codetext
Türöffnung | H2 Ebene +3 | 1263Tür0812546793 | m² |  | Trockenbauarbeiten | Türöffnung |  | 11.25 |  | 1263Wa 0812546960 | AllplanAttributes - Codetext: Codetext; Türanschlag: DIN R; Attributset-Objekt: OpeningElement; Pset_OpeningElementCommon - FireExit: no; Reference: Codetext
Türöffnung | H2 Ebene +3 | 1263Tür0812593397 | m² |  | Trockenbauarbeiten | Türöffnung |  | 11.25 |  | 1263Wa 0812593412 | AllplanAttributes - Codetext: Codetext; Türanschlag: DIN R; Attributset-Objekt: OpeningElement; Pset_OpeningElementCommon - FireExit: no; Reference: Codetext
Türöffnung | H2 Ebene +3 | 1263Tür0812843161 | m² |  | Trockenbauarbeiten | Türöffnung |  | 11.25 |  | 1263Wa 0812843244 | AllplanAttributes - Codetext: Codetext; Türanschlag: DIN L; Attributset-Objekt: OpeningElement; Pset_OpeningElementCommon - FireExit: no; Reference: Codetext
Türöffnung | H2 Ebene +3 | 1263Tür0812975240 | m² |  | Trockenbauarbeiten | Türöffnung |  | 11.25 |  | 1263Wa 0812843244 | AllplanAttributes - Codetext: Codetext; Türanschlag: DIN R; Attributset-Objekt: OpeningElement; Pset_OpeningElementCommon - FireExit: no; Reference: Codetext
Türöffnung | H2 Ebene +3 | 1263Tür0812840388 | m² |  | Trockenbauarbeiten | Türöffnung |  | 11.25 |  | 1263Wa 0812824831 | AllplanAttributes - Codetext: Codetext; Türanschlag: DIN R; Attributset-Objekt: OpeningElement; Pset_OpeningElementCommon - FireExit: no; Reference: Codetext
Türöffnung | H2 Ebene +3 | 1263Tür0812839290 | m² |  | Trockenbauarbeiten | Türöffnung |  | 11.25 |  | 1263Wa 0812839292 | AllplanAttributes - Codetext: Codetext; Türanschlag: DIN R; Attributset-Objekt: OpeningElement; Pset_OpeningElementCommon - FireExit: no; Reference: Codetext
Türöffnung | H2 Ebene +3 | 1263Tür0812772359 | m² |  | Trockenbauarbeiten | Türöffnung |  | 11.25 |  | 1263Wa 0812594458 | AllplanAttributes - Codetext: Codetext; Türanschlag: DIN L; Attributset-Objekt: OpeningElement; Pset_OpeningElementCommon - FireExit: no; Reference: Codetext
Türöffnung | H2 Ebene +3 | 1263Tür0812839954 | m² |  | Trockenbauarbeiten | Türöffnung |  | 11.25 |  | 1263Wa 0812824838 | AllplanAttributes - Codetext: Codetext; Türanschlag: DIN L; Attributset-Objekt: OpeningElement; Pset_OpeningElementCommon - FireExit: no; Reference: Codetext
Wandnische | H2 Ebene +3 | 1263Wni0813010383 | m² | 0 | Zimmer- und Holzbauarbeiten | Wandnische | 0 |  | NEW
Türöffnung | H2 Ebene +3 | 1263Tür0812750343 | m² |  | Trockenbauarbeiten | Türöffnung |  | 11.25 | NEW | 1263Wa 0812550822 | EI2 30 | AllplanAttributes - Codetext: Codetext; Türanschlag: DIN R; Attributset-Objekt: OpeningElement; Rauchschutz: yes; Selbstschließend: yes; ash T_Zulage Schachttür: no; ash T_Dichtschließend: no; ash T_Feststellanlage (FSA): -; ash T_nicht abschließbar: no; Pset_OpeningElementCommon - FireExit: no; Reference: Codetext
Türöffnung | H2 Ebene +3 | 1263Tür0812996113 | m² | 0 | Trockenbauarbeiten | Türöffnung | 0 |  | NEW | AllplanAttributes - Türanschlag: DIN R
Türöffnung | H2 Ebene +3 | 1263Tür0812964140 | m² | 0 | Zimmer- und Holzbauarbeiten | Türöffnung | 0 | 0 | NEW | 1113Wa 0812447364 | E 60 | AllplanAttributes - Türanschlag: -; Text1: 15b; Positionsnummer_Text: S68
Türöffnung | H2 Ebene +3 | 1263Tür0812964139 | m² | -340 | Zimmer- und Holzbauarbeiten | Türöffnung | 0 | 0 | NEW | 1113Wa 0812843889 | AllplanAttributes - Türanschlag: -; Positionsnummer_Text: S68
Türöffnung | H2 Ebene +3 | 1263Tür0812546052 | m² |  | Trockenbauarbeiten | Türöffnung |  | 11.25 | NEW | 1263Wa 0812546974 | E 60 | AllplanAttributes - Türanschlag: -
Türöffnung | H2 Ebene +3 | 1263Tür0812820842 | m² | 0 | Trockenbauarbeiten | Türöffnung | 0 | 11.25 | NEW | 1263Wa 0812820817 | AllplanAttributes - Türanschlag: -
Türöffnung | H2 Ebene +3 | 1263Tür0812546145 | m² | 0 | Trockenbauarbeiten | Türöffnung | 0 | 11.25 |  | 1263Wa 0812547241 | AllplanAttributes - Codetext: Codetext; Türanschlag: DIN L; Attributset-Objekt: OpeningElement; Ortscode_Geschoßbezeichnung: E03; Pset_OpeningElementCommon - FireExit: no; Reference: Codetext
Türöffnung | H2 Ebene +3 | 1263Tür0813064809 | m² |  | Trockenbauarbeiten | Türöffnung |  | 11.25 | NEW | 1263Wa 0812787100 | EI2 30 | AllplanAttributes - Codetext: Codetext; Türanschlag: DIN R; Attributset-Objekt: OpeningElement; Rauchschutz: yes; Selbstschließend: yes; ash T_Zulage Schachttür: no; ash T_Dichtschließend: no; ash T_Feststellanlage (FSA): -; ash T_nicht abschließbar: no; Pset_OpeningElementCommon - FireExit: no; Reference: Codetext
Türöffnung | H2 Ebene +3 | 1263Tür0813064813 | m² | 0 | Trockenbauarbeiten | Türöffnung | 0 |  | NEW | AllplanAttributes - Türanschlag: DIN R
Türöffnung | H2 Ebene +3 | 1263Tür0812906744 | m² |  | Trockenbauarbeiten | Türöffnung |  | 11.25 | NEW | 1263Wa 0812906747 | AllplanAttributes - Türanschlag: -
Deckendurchbruch | H2 Ebene +3 |  |  |  |  |  |  |  | NEW | AllplanAttributes - Object Layer Attributes #1, Gewerk: Betonarbeiten; Object Layer Attributes #1, Allright_Bauteil_ID: 1264Ddu0812686928; Object Layer Attributes #1, Abrechnungsart: m²; Object Layer Attributes #1, Objektname: Deckendurchbruch
Deckendurchbruch | H2 Ebene +3 |  |  |  |  |  |  |  | NEW | AllplanAttributes - Object Layer Attributes #1, Gewerk: Betonarbeiten; Object Layer Attributes #1, Allright_Bauteil_ID: 1264Ddu0812686933; Object Layer Attributes #1, Abrechnungsart: m²; Object Layer Attributes #1, Objektname: Deckendurchbruch
Fensteröffnung | H2 Ebene +2 | 1205Fen0000280262 | m² | 0 | Fensterarbeiten | Fensteröffnung | 0 | 7.5 |  | 1205Wa 0000003844 | 0 | - | 0,51 | AllplanAttributes - ash D_Detailverweis: <undefiniert>; U-Wert: 0.9; Schallschutzklasse: 32; Sonnenschutztyp: Movable
Fensteröffnung | H2 Ebene +2 | 1205Fen0000280304 | m² | 0 | Fensterarbeiten | Fensteröffnung | 0 | 7.5 |  | 1205Wa 0000003844 | 0 | - | 0,51 | AllplanAttributes - ash D_Detailverweis: <undefiniert>; U-Wert: 0.9; Schallschutzklasse: 32; Sonnenschutztyp: Movable
Fensteröffnung | H2 Ebene +2 | 1205Fen0000280139 | m² | 0 | Fensterarbeiten | Fensteröffnung | 0 | 7.5 |  | 1205Wa 0000003844 | 0 | - | 0,51 | AllplanAttributes - ash D_Detailverweis: <undefiniert>; U-Wert: 0.9; Schallschutzklasse: 32; Sonnenschutztyp: Movable
Fensteröffnung | H2 Ebene +2 | 1205Fen0000280145 | m² | 0 | Fensterarbeiten | Fensteröffnung | 0 | 7.5 |  | 1205Wa 0000003844 | 0 | - | 0,51 | AllplanAttributes - ash D_Detailverweis: <undefiniert>; U-Wert: 0.9; Schallschutzklasse: 32; Sonnenschutztyp: Movable
Fensteröffnung | H2 Ebene +2 | 1205Fen0000280196 | m² | 0 | Fensterarbeiten | Fensteröffnung | 0 | 7.5 |  | 1205Wa 0000003844 | 0 | - | 0,51 | AllplanAttributes - ash D_Detailverweis: <undefiniert>; U-Wert: 0.9; Schallschutzklasse: 32; Sonnenschutztyp: Movable
Fensteröffnung | H2 Ebene +2 | 1205Fen0000280307 | m² | 0 | Fensterarbeiten | Fensteröffnung | 0 | 7.5 |  | 1205Wa 0000003844 | 0 | - | 0,51 | AllplanAttributes - ash D_Detailverweis: <undefiniert>; U-Wert: 0.9; Schallschutzklasse: 32; Sonnenschutztyp: Movable
Fensteröffnung | H2 Ebene +2 | 1205Fen0000280535 | m³ | 0 | Fensterarbeiten | Fensteröffnung | 0 | 7.5 |  | 1205Wa 0000003834 | 0 | - | 0,51 | AllplanAttributes - ash D_Detailverweis: <undefiniert>; U-Wert: 0.9; Schallschutzklasse: 32; Sonnenschutztyp: Movable
Fensteröffnung | H2 Ebene +2 | 1205Fen0000280613 | m³ | 0 | Fensterarbeiten | Fensteröffnung | 0 | 7.5 |  | 1205Wa 0000003834 | 0 | - | 0,51 | AllplanAttributes - ash D_Detailverweis: <undefiniert>; U-Wert: 0.9; Schallschutzklasse: 32; Sonnenschutztyp: Movable
Fensteröffnung | H2 Ebene +2 | 1205Fen0000280619 | m³ | 0 | Fensterarbeiten | Fensteröffnung | 0 | 7.5 |  | 1205Wa 0000003834 | 0 | - | 0,51 | AllplanAttributes - ash D_Detailverweis: <undefiniert>; U-Wert: 0.9; Schallschutzklasse: 32; Sonnenschutztyp: Movable
Fensteröffnung | H2 Ebene +2 | 1205Fen0000281117 | m³ | 0 | Fensterarbeiten | Fensteröffnung | 0 | 7.5 |  | 1205Wa 0000003834 | 0 | - | 0,51 | AllplanAttributes - ash D_Detailverweis: <undefiniert>; U-Wert: 0.9; Schallschutzklasse: 32; Sonnenschutztyp: Movable
Fensteröffnung | H2 Ebene +2 | 1205Fen0000280709 | m³ | 0 | Fensterarbeiten | Fensteröffnung | 0 | 7.5 |  | 1205Wa 0000003834 | 0 | - | 0,51 | AllplanAttributes - ash D_Detailverweis: <undefiniert>; U-Wert: 0.9; Schallschutzklasse: 32; Sonnenschutztyp: Movable
Fensteröffnung | H2 Ebene +2 | 1205Fen0000281053 | m³ | 0 | Fensterarbeiten | Fensteröffnung | 0 | 7.5 |  | 1205Wa 0000003834 | 0 | - | 0,51 | AllplanAttributes - ash D_Detailverweis: <undefiniert>; U-Wert: 0.9; Schallschutzklasse: 32; Sonnenschutztyp: Movable
Fensteröffnung | H2 Ebene +2 | 1205Fen0000280467 | m³ | 0 | Fensterarbeiten | Fensteröffnung | 0 | 7.5 |  | 1205Wa 0000003824 | 0 | - | 0,51 | AllplanAttributes - ash D_Detailverweis: <undefiniert>; U-Wert: 0.9; Schallschutzklasse: 32; Sonnenschutztyp: Movable
Fensteröffnung | H2 Ebene +2 | 1205Fen0000281119 | m³ | 0 | Fensterarbeiten | Fensteröffnung | 0 | 7.5 |  | 1205Wa 0000003824 | 0 | - | 0,51 | AllplanAttributes - ash D_Detailverweis: <undefiniert>; U-Wert: 0.9; Schallschutzklasse: 32; Sonnenschutztyp: Movable
Fensteröffnung | H2 Ebene +2 | 1205Fen0000280435 | m³ | 0 | Fensterarbeiten | Fensteröffnung | 0 | 7.5 |  | 1205Wa 0000003824 | 0 | - | 0,51 | AllplanAttributes - ash D_Detailverweis: <undefiniert>; U-Wert: 0.9; Schallschutzklasse: 32; Sonnenschutztyp: Movable
Fensteröffnung | H2 Ebene +2 | 1205Fen0000281169 | m³ | 0 | Fensterarbeiten | Fensteröffnung | 0 | 7.5 |  | 1205Wa 0000003824 | 0 | - | 0,51 | AllplanAttributes - ash D_Detailverweis: <undefiniert>; U-Wert: 0.9; Schallschutzklasse: 32; Sonnenschutztyp: Movable
Fensteröffnung | H2 Ebene +2 | 1205Fen0000280515 | m³ | 0 | Fensterarbeiten | Fensteröffnung | 0 | 7.5 |  | 1205Wa 0000003824 | 0 | - | 0,51 | AllplanAttributes - ash D_Detailverweis: <undefiniert>; U-Wert: 0.9; Schallschutzklasse: 32; Sonnenschutztyp: Movable
Fensteröffnung | H2 Ebene +2 | 1205Fen0000281189 | m³ | 0 | Fensterarbeiten | Fensteröffnung | 0 | 7.5 |  | 1205Wa 0000003824 | 0 | - | 0,51 | AllplanAttributes - ash D_Detailverweis: <undefiniert>; U-Wert: 0.9; Schallschutzklasse: 32; Sonnenschutztyp: Movable
Fensteröffnung | H2 Ebene +2 | 1205Fen0000280587 | m² | 0 | Fensterarbeiten | Fensteröffnung | 0 | 7.5 |  | 1205Wa 0000003814 | 0 | - | 0,51 | AllplanAttributes - ash D_Detailverweis: <undefiniert>; U-Wert: 0.9; Schallschutzklasse: 32; Sonnenschutztyp: Movable
Fensteröffnung | H2 Ebene +2 | 1205Fen0000281167 | m² | 0 | Fensterarbeiten | Fensteröffnung | 0 | 7.5 |  | 1205Wa 0000003814 | 0 | - | 0,51 | AllplanAttributes - ash D_Detailverweis: <undefiniert>; U-Wert: 0.9; Schallschutzklasse: 32; Sonnenschutztyp: Movable
Fensteröffnung | H2 Ebene +2 | 1205Fen0000281023 | m² | 0 | Fensterarbeiten | Fensteröffnung | 0 | 7.5 |  | 1205Wa 0000003814 | 0 | - | 0,51 | AllplanAttributes - ash D_Detailverweis: <undefiniert>; U-Wert: 0.9; Schallschutzklasse: 32; Sonnenschutztyp: Movable
Fensteröffnung | H2 Ebene +2 | 1205Fen0000281127 | m² | 0 | Fensterarbeiten | Fensteröffnung | 0 | 7.5 |  | 1205Wa 0000003814 | 0 | - | 0,51 | AllplanAttributes - ash D_Detailverweis: <undefiniert>; U-Wert: 0.9; Schallschutzklasse: 32; Sonnenschutztyp: Movable
Fensteröffnung | H2 Ebene +2 | 1205Fen0000281177 | m² | 0 | Fensterarbeiten | Fensteröffnung | 0 | 7.5 |  | 1205Wa 0000003814 | 0 | - | 0,51 | AllplanAttributes - ash D_Detailverweis: <undefiniert>; U-Wert: 0.9; Schallschutzklasse: 32; Sonnenschutztyp: Movable
Fensteröffnung | H2 Ebene +2 | 1205Fen0000280635 | m² | 0 | Fensterarbeiten | Fensteröffnung | 0 | 7.5 |  | 1205Wa 0000003814 | 0 | - | 0,51 | AllplanAttributes - ash D_Detailverweis: <undefiniert>; U-Wert: 0.9; Schallschutzklasse: 32; Sonnenschutztyp: Movable
Fensteröffnung | H2 Ebene +2 | 1205Fen0000281003 | m² | 0 | Fensterarbeiten | Fensteröffnung | 0 | 7.5 | NEW | 1205Wa 0000003804 | 0 | - | 0,51 | AllplanAttributes - ash D_Detailverweis: <undefiniert>; U-Wert: 0.9; Schallschutzklasse: 32; Sonnenschutztyp: Movable
Fensteröffnung | H2 Ebene +2 | 1205Fen0000280799 | m² | 0 | Fensterarbeiten | Fensteröffnung | 0 | 7.5 | NEW | 1205Wa 0000003804 | 0 | - | 0,51 | AllplanAttributes - ash D_Detailverweis: <undefiniert>; U-Wert: 0.9; Schallschutzklasse: 32; Sonnenschutztyp: Movable
Fensteröffnung | H2 Ebene +2 | 1205Fen0000280659 | m² | 0 | Fensterarbeiten | Fensteröffnung | 0 | 7.5 | NEW | 1205Wa 0000003804 | 0 | - | 0,51 | AllplanAttributes - ash D_Detailverweis: <undefiniert>; U-Wert: 0.9; Schallschutzklasse: 32; Sonnenschutztyp: Movable
Fensteröffnung | H2 Ebene +2 | 1205Fen0000280509 | m² | 0 | Fensterarbeiten | Fensteröffnung | 0 | 7.5 | NEW | 1205Wa 0000003804 | 0 | - | 0,51 | AllplanAttributes - ash D_Detailverweis: <undefiniert>; U-Wert: 0.9; Schallschutzklasse: 32; Sonnenschutztyp: Movable
Fensteröffnung | H2 Ebene +2 | 1205Fen0000280979 | m² | 0 | Fensterarbeiten | Fensteröffnung | 0 | 7.5 | NEW | 1205Wa 0000003804 | 0 | - | 0,51 | AllplanAttributes - ash D_Detailverweis: <undefiniert>; U-Wert: 0.9; Schallschutzklasse: 32; Sonnenschutztyp: Movable
Fensteröffnung | H2 Ebene +2 | 1205Fen0000280873 | m² | 0 | Fensterarbeiten | Fensteröffnung | 0 | 7.5 | NEW | 1205Wa 0000003804 | 0 | - | 0,51 | AllplanAttributes - ash D_Detailverweis: <undefiniert>; U-Wert: 0.9; Schallschutzklasse: 32; Sonnenschutztyp: Movable
Fensteröffnung | H2 Ebene +2 | 1205Fen0000280541 | m² | 0 | Fensterarbeiten | Fensteröffnung | 0 | 7.5 | NEW | 1205Wa 0000003794 | 0 | - | 0,51 | AllplanAttributes - ash D_Detailverweis: <undefiniert>; U-Wert: 0.9; Schallschutzklasse: 32; Sonnenschutztyp: Movable
Fensteröffnung | H2 Ebene +2 | 1205Fen0000280977 | m² | 0 | Fensterarbeiten | Fensteröffnung | 0 | 7.5 | NEW | 1205Wa 0000003794 | 0 | - | 0,51 | AllplanAttributes - ash D_Detailverweis: <undefiniert>; U-Wert: 0.9; Schallschutzklasse: 32; Sonnenschutztyp: Movable
Fensteröffnung | H2 Ebene +2 | 1205Fen0000280773 | m² | 0 | Fensterarbeiten | Fensteröffnung | 0 | 7.5 | NEW | 1205Wa 0000003794 | 0 | - | 0,51 | AllplanAttributes - ash D_Detailverweis: <undefiniert>; U-Wert: 0.9; Schallschutzklasse: 32; Sonnenschutztyp: Movable
Fensteröffnung | H2 Ebene +2 | 1205Fen0000280569 | m² | 0 | Fensterarbeiten | Fensteröffnung | 0 | 7.5 | NEW | 1205Wa 0000003794 | 0 | - | 0,51 | AllplanAttributes - ash D_Detailverweis: <undefiniert>; U-Wert: 0.9; Schallschutzklasse: 32; Sonnenschutztyp: Movable
Fensteröffnung | H2 Ebene +2 | 1205Fen0000281025 | m² | 0 | Fensterarbeiten | Fensteröffnung | 0 | 7.5 | NEW | 1205Wa 0000003794 | 0 | - | 0,51 | AllplanAttributes - ash D_Detailverweis: <undefiniert>; U-Wert: 0.9; Schallschutzklasse: 32; Sonnenschutztyp: Movable
Fensteröffnung | H2 Ebene +2 | 1205Fen0000280431 | m² | 0 | Fensterarbeiten | Fensteröffnung | 0 | 7.5 | NEW | 1205Wa 0000003794 | 0 | - | 0,51 | AllplanAttributes - ash D_Detailverweis: <undefiniert>; U-Wert: 0.9; Schallschutzklasse: 32; Sonnenschutztyp: Movable
Fensteröffnung | H2 Ebene +2 | 1205Fen0000280471 | m² | 0 | Fensterarbeiten | Fensteröffnung | 0 | 7.5 | NEW | 1205Wa 0000003784 | 0 | - | 0,51 | AllplanAttributes - ash D_Detailverweis: <undefiniert>; U-Wert: 0.9; Schallschutzklasse: 32; Sonnenschutztyp: Movable
Fensteröffnung | H2 Ebene +2 | 1205Fen0000280757 | m² | 0 | Fensterarbeiten | Fensteröffnung | 0 | 7.5 | NEW | 1205Wa 0000003784 | 0 | - | 0,51 | AllplanAttributes - ash D_Detailverweis: <undefiniert>; U-Wert: 0.9; Schallschutzklasse: 32; Sonnenschutztyp: Movable
Fensteröffnung | H2 Ebene +2 | 1205Fen0000280579 | m² | 0 | Fensterarbeiten | Fensteröffnung | 0 | 7.5 | NEW | 1205Wa 0000003784 | 0 | - | 0,51 | AllplanAttributes - ash D_Detailverweis: <undefiniert>; U-Wert: 0.9; Schallschutzklasse: 32; Sonnenschutztyp: Movable
Fensteröffnung | H2 Ebene +2 | 1205Fen0000280401 | m² | 0 | Fensterarbeiten | Fensteröffnung | 0 | 7.5 | NEW | 1205Wa 0000003784 | 0 | - | 0,51 | AllplanAttributes - ash D_Detailverweis: <undefiniert>; U-Wert: 0.9; Schallschutzklasse: 32; Sonnenschutztyp: Movable
Fensteröffnung | H2 Ebene +2 | 1205Fen0000280631 | m² | 0 | Fensterarbeiten | Fensteröffnung | 0 | 7.5 | NEW | 1205Wa 0000003784 | 0 | - | 0,51 | AllplanAttributes - ash D_Detailverweis: <undefiniert>; U-Wert: 0.9; Schallschutzklasse: 32; Sonnenschutztyp: Movable
Fensteröffnung | H2 Ebene +2 | 1205Fen0000280605 | m² | 0 | Fensterarbeiten | Fensteröffnung | 0 | 7.5 | NEW | 1205Wa 0000003784 | 0 | - | 0,51 | AllplanAttributes - ash D_Detailverweis: <undefiniert>; U-Wert: 0.9; Schallschutzklasse: 32; Sonnenschutztyp: Movable
Fensteröffnung | H2 Ebene +2 | 1205Fen0000279968 | m² |  | Wärmedämm-Verbundsysteme | Fensteröffnung |  | 7.5 | NEW | 1205Wa 0000001868 | 0 | - | 0,51 | AllplanAttributes - Material: Fensterelement; Tragendes Bauteil: no; Brandabschnittsdefinierendes Bauteil: no; ash D_Detailverweis: <undefiniert>; U-Wert: 0.9; Schallschutzklasse: 32; Sonnenschutztyp: Movable
Fensteröffnung | H2 Ebene +2 | 1205Fen0000279980 | m³ | 0 | Wärmedämm-Verbundsysteme | Fensteröffnung | 0 | 7.5 | NEW | 1205Wa 0000001872 | 0 | - | 0,51 | AllplanAttributes - Material: Fensterelement; Außenliegend: yes; ash D_Detailverweis: <undefiniert>; U-Wert: 0.9; Schallschutzklasse: 32; Sonnenschutztyp: Movable
Fensteröffnung | H2 Ebene +2 | 1205Fen0000279990 | m³ | 0 | Wärmedämm-Verbundsysteme | Fensteröffnung | 0 | 7.5 | NEW | 1205Wa 0000001876 | 0 | - | 0,51 | AllplanAttributes - ash D_Detailverweis: <undefiniert>; U-Wert: 0.9; Schallschutzklasse: 32; Sonnenschutztyp: Movable
Fensteröffnung | H2 Ebene +2 | 1205Fen0000279963 | m² | 0 | Wärmedämm-Verbundsysteme | Fensteröffnung | 0 | 7.5 | NEW | 1205Wa 0000001880 | 0 | - | 0,51 | AllplanAttributes - ash D_Detailverweis: <undefiniert>; U-Wert: 0.9; Schallschutzklasse: 32; Sonnenschutztyp: Movable
Fensteröffnung | H2 Ebene +2 | 1205Fen0000280903 | m² | 0 | Wärmedämm-Verbundsysteme | Fensteröffnung | 0 | 7.5 | NEW | 1205Wa 0000001884 | 0 | - | 0,51 | AllplanAttributes - ash D_Detailverweis: <undefiniert>; U-Wert: 0.9; Schallschutzklasse: 32; Sonnenschutztyp: Movable
Fensteröffnung | H2 Ebene +2 | 1205Fen0000281231 | m² | 0 | Wärmedämm-Verbundsysteme | Fensteröffnung | 0 | 7.5 | NEW | 1205Wa 0000001888 | 0 | - | 0,51 | AllplanAttributes - ash D_Detailverweis: <undefiniert>; U-Wert: 0.9; Schallschutzklasse: 32; Sonnenschutztyp: Movable
Fensteröffnung | H2 Ebene +2 | 1205Fen0000281193 | m² | 0 | Wärmedämm-Verbundsysteme | Fensteröffnung | 0 | 7.5 | NEW | 1205Wa 0000001892 | 0 | - | 0,51 | AllplanAttributes - ash D_Detailverweis: <undefiniert>; U-Wert: 0.9; Schallschutzklasse: 32; Sonnenschutztyp: Movable
Fensteröffnung | H2 Ebene +2 | 1205Fen0000280163 | m² |  | Wärmedämm-Verbundsysteme | Fensteröffnung |  | 7.5 | NEW | 1205Wa 0000001193 | 0 | - | 0,51 | AllplanAttributes - Material: Fensterelement; Tragendes Bauteil: no; Brandabschnittsdefinierendes Bauteil: no; ash D_Detailverweis: <undefiniert>; U-Wert: 0.9; Schallschutzklasse: 32; Sonnenschutztyp: Movable
Fensteröffnung | H2 Ebene +2 | 1205Fen0000281219 | m³ | 0 | Wärmedämm-Verbundsysteme | Fensteröffnung | 0 | 7.5 | NEW | 1205Wa 0000001197 | 0 | - | 0,51 | AllplanAttributes - Material: Fensterelement; Außenliegend: yes; ash D_Detailverweis: <undefiniert>; U-Wert: 0.9; Schallschutzklasse: 32; Sonnenschutztyp: Movable
Fensteröffnung | H2 Ebene +2 | 1205Fen0000280993 | m³ | 0 | Wärmedämm-Verbundsysteme | Fensteröffnung | 0 | 7.5 | NEW | 1205Wa 0000001201 | 0 | - | 0,51 | AllplanAttributes - ash D_Detailverweis: <undefiniert>; U-Wert: 0.9; Schallschutzklasse: 32; Sonnenschutztyp: Movable
Fensteröffnung | H2 Ebene +2 | 1205Fen0000281039 | m² | 0 | Wärmedämm-Verbundsysteme | Fensteröffnung | 0 | 7.5 | NEW | 1205Wa 0000001205 | 0 | - | 0,51 | AllplanAttributes - ash D_Detailverweis: <undefiniert>; U-Wert: 0.9; Schallschutzklasse: 32; Sonnenschutztyp: Movable
Fensteröffnung | H2 Ebene +2 | 1205Fen0000280625 | m² | 0 | Wärmedämm-Verbundsysteme | Fensteröffnung | 0 | 7.5 | NEW | 1205Wa 0000001209 | 0 | - | 0,51 | AllplanAttributes - ash D_Detailverweis: <undefiniert>; U-Wert: 0.9; Schallschutzklasse: 32; Sonnenschutztyp: Movable
Fensteröffnung | H2 Ebene +2 | 1205Fen0000280761 | m² | 0 | Wärmedämm-Verbundsysteme | Fensteröffnung | 0 | 7.5 | NEW | 1205Wa 0000001213 | 0 | - | 0,51 | AllplanAttributes - ash D_Detailverweis: <undefiniert>; U-Wert: 0.9; Schallschutzklasse: 32; Sonnenschutztyp: Movable
Fensteröffnung | H2 Ebene +2 | 1205Fen0000280529 | m² | 0 | Wärmedämm-Verbundsysteme | Fensteröffnung | 0 | 7.5 | NEW | 1205Wa 0000001217 | 0 | - | 0,51 | AllplanAttributes - ash D_Detailverweis: FS 1; ash D_Plannummer: D780; U-Wert: 0.9; Schallschutzklasse: 32; Sonnenschutztyp: Movable
Fensteröffnung | H2 Ebene +2 | 1205Fen0000280241 | m² |  | Wärmedämm-Verbundsysteme | Fensteröffnung |  | 7.5 | NEW | 1205Wa 0000001159 | 0 | - | 0,51 | AllplanAttributes - Material: Fensterelement; Tragendes Bauteil: no; Brandabschnittsdefinierendes Bauteil: no; ash D_Detailverweis: <undefiniert>; U-Wert: 0.9; Schallschutzklasse: 35; Sonnenschutztyp: Movable
Fensteröffnung | H2 Ebene +2 | 1205Fen0000280154 | m² |  | Wärmedämm-Verbundsysteme | Fensteröffnung |  | 7.5 | NEW | 1205Wa 0000001159 | 0 | - | 0,51 | AllplanAttributes - Material: Fensterelement; Tragendes Bauteil: no; Brandabschnittsdefinierendes Bauteil: no; ash D_Detailverweis: <undefiniert>; U-Wert: 0.9; Schallschutzklasse: 35; Sonnenschutztyp: Movable
Fensteröffnung | H2 Ebene +2 | 1205Fen0000281097 | m³ | 0 | Wärmedämm-Verbundsysteme | Fensteröffnung | 0 | 7.5 | NEW | 1205Wa 0000001155 | 0 | - | 0,51 | AllplanAttributes - Material: Fensterelement; Außenliegend: yes; ash D_Detailverweis: <undefiniert>; U-Wert: 0.9; Schallschutzklasse: 35; Sonnenschutztyp: Movable
Fensteröffnung | H2 Ebene +2 | 1205Fen0000280621 | m³ | 0 | Wärmedämm-Verbundsysteme | Fensteröffnung | 0 | 7.5 | NEW | 1205Wa 0000001155 | 0 | - | 0,51 | AllplanAttributes - Material: Fensterelement; Außenliegend: yes; ash D_Detailverweis: <undefiniert>; U-Wert: 0.9; Schallschutzklasse: 35; Sonnenschutztyp: Movable
Fensteröffnung | H2 Ebene +2 | 1205Fen0000281229 | m³ | 0 | Wärmedämm-Verbundsysteme | Fensteröffnung | 0 | 7.5 | NEW | 1205Wa 0000001135 | 0 | - | 0,51 | AllplanAttributes - ash D_Detailverweis: <undefiniert>; U-Wert: 0.9; Schallschutzklasse: 35; Sonnenschutztyp: Movable
Fensteröffnung | H2 Ebene +2 | 1205Fen0000281149 | m³ | 0 | Wärmedämm-Verbundsysteme | Fensteröffnung | 0 | 7.5 | NEW | 1205Wa 0000001135 | 0 | - | 0,51 | AllplanAttributes - ash D_Detailverweis: <undefiniert>; U-Wert: 0.9; Schallschutzklasse: 35; Sonnenschutztyp: Movable
Fensteröffnung | H2 Ebene +2 | 1205Fen0000280917 | m² | 0 | Wärmedämm-Verbundsysteme | Fensteröffnung | 0 | 7.5 | NEW | 1205Wa 0000001139 | 0 | - | 0,51 | AllplanAttributes - ash D_Detailverweis: <undefiniert>; U-Wert: 0.9; Schallschutzklasse: 35; Sonnenschutztyp: Movable
Fensteröffnung | H2 Ebene +2 | 1205Fen0000280487 | m² | 0 | Wärmedämm-Verbundsysteme | Fensteröffnung | 0 | 7.5 | NEW | 1205Wa 0000001139 | 0 | - | 0,51 | AllplanAttributes - ash D_Detailverweis: <undefiniert>; U-Wert: 0.9; Schallschutzklasse: 35; Sonnenschutztyp: Movable
Fensteröffnung | H2 Ebene +2 | 1205Fen0000281197 | m² | 0 | Wärmedämm-Verbundsysteme | Fensteröffnung | 0 | 7.5 | NEW | 1205Wa 0000001143 | 0 | - | 0,51 | AllplanAttributes - ash D_Detailverweis: <undefiniert>; U-Wert: 0.9; Schallschutzklasse: 35; Sonnenschutztyp: Movable
Fensteröffnung | H2 Ebene +2 | 1205Fen0000280675 | m² | 0 | Wärmedämm-Verbundsysteme | Fensteröffnung | 0 | 7.5 | NEW | 1205Wa 0000001143 | 0 | - | 0,51 | AllplanAttributes - ash D_Detailverweis: <undefiniert>; U-Wert: 0.9; Schallschutzklasse: 35; Sonnenschutztyp: Movable
Fensteröffnung | H2 Ebene +2 | 1205Fen0000281221 | m² | 0 | Wärmedämm-Verbundsysteme | Fensteröffnung | 0 | 7.5 | NEW | 1205Wa 0000001147 | 0 | - | 0,51 | AllplanAttributes - ash D_Detailverweis: <undefiniert>; U-Wert: 0.9; Schallschutzklasse: 35; Sonnenschutztyp: Movable
Fensteröffnung | H2 Ebene +2 | 1205Fen0000281045 | m² | 0 | Wärmedämm-Verbundsysteme | Fensteröffnung | 0 | 7.5 | NEW | 1205Wa 0000001147 | 0 | - | 0,51 | AllplanAttributes - ash D_Detailverweis: <undefiniert>; U-Wert: 0.9; Schallschutzklasse: 35; Sonnenschutztyp: Movable
Fensteröffnung | H2 Ebene +2 | 1205Fen0000280785 | m² | 0 | Wärmedämm-Verbundsysteme | Fensteröffnung | 0 | 7.5 | NEW | 1205Wa 0000001151 | 0 | - | 0,51 | AllplanAttributes - ash D_Detailverweis: <undefiniert>; U-Wert: 0.9; Schallschutzklasse: 35; Sonnenschutztyp: Movable
Fensteröffnung | H2 Ebene +2 | 1205Fen0000280567 | m² | 0 | Wärmedämm-Verbundsysteme | Fensteröffnung | 0 | 7.5 | NEW | 1205Wa 0000001151 | 0 | - | 0,51 | AllplanAttributes - ash D_Detailverweis: <undefiniert>; U-Wert: 0.9; Schallschutzklasse: 35; Sonnenschutztyp: Movable
Fensteröffnung | H2 Ebene +2 | 1205Fen0000280175 | m² |  | Wärmedämm-Verbundsysteme | Fensteröffnung |  | 7.5 | NEW | 1205Wa 0000003112 | 0 | - | 0,51 | AllplanAttributes - Material: Fensterelement; Tragendes Bauteil: no; Brandabschnittsdefinierendes Bauteil: no; ash D_Detailverweis: <undefiniert>; U-Wert: 0.9; Schallschutzklasse: 35; Sonnenschutztyp: Movable
Fensteröffnung | H2 Ebene +2 | 1205Fen0000280238 | m² |  | Wärmedämm-Verbundsysteme | Fensteröffnung |  | 7.5 | NEW | 1205Wa 0000003112 | 0 | - | 0,51 | AllplanAttributes - Material: Fensterelement; Tragendes Bauteil: no; Brandabschnittsdefinierendes Bauteil: no; ash D_Detailverweis: <undefiniert>; U-Wert: 0.9; Schallschutzklasse: 35; Sonnenschutztyp: Movable
Fensteröffnung | H2 Ebene +2 | 1205Fen0000280881 | m³ | 0 | Wärmedämm-Verbundsysteme | Fensteröffnung | 0 | 7.5 | NEW | 1205Wa 0000003108 | 0 | - | 0,51 | AllplanAttributes - Material: Fensterelement; Außenliegend: yes; ash D_Detailverweis: <undefiniert>; U-Wert: 0.9; Schallschutzklasse: 35; Sonnenschutztyp: Movable
Fensteröffnung | H2 Ebene +2 | 1205Fen0000280565 | m³ | 0 | Wärmedämm-Verbundsysteme | Fensteröffnung | 0 | 7.5 | NEW | 1205Wa 0000003108 | 0 | - | 0,51 | AllplanAttributes - Material: Fensterelement; Außenliegend: yes; ash D_Detailverweis: <undefiniert>; U-Wert: 0.9; Schallschutzklasse: 35; Sonnenschutztyp: Movable
Fensteröffnung | H2 Ebene +2 | 1205Fen0000280739 | m³ | 0 | Wärmedämm-Verbundsysteme | Fensteröffnung | 0 | 7.5 | NEW | 1205Wa 0000003104 | 0 | - | 0,51 | AllplanAttributes - ash D_Detailverweis: <undefiniert>; U-Wert: 0.9; Schallschutzklasse: 35; Sonnenschutztyp: Movable
Fensteröffnung | H2 Ebene +2 | 1205Fen0000280861 | m³ | 0 | Wärmedämm-Verbundsysteme | Fensteröffnung | 0 | 7.5 | NEW | 1205Wa 0000003104 | 0 | - | 0,51 | AllplanAttributes - ash D_Detailverweis: <undefiniert>; U-Wert: 0.9; Schallschutzklasse: 35; Sonnenschutztyp: Movable
Fensteröffnung | H2 Ebene +2 | 1205Fen0000280549 | m² | 0 | Wärmedämm-Verbundsysteme | Fensteröffnung | 0 | 7.5 | NEW | 1205Wa 0000003100 | 0 | - | 0,51 | AllplanAttributes - ash D_Detailverweis: <undefiniert>; U-Wert: 0.9; Schallschutzklasse: 35; Sonnenschutztyp: Movable
Fensteröffnung | H2 Ebene +2 | 1205Fen0000280997 | m² | 0 | Wärmedämm-Verbundsysteme | Fensteröffnung | 0 | 7.5 | NEW | 1205Wa 0000003100 | 0 | - | 0,51 | AllplanAttributes - ash D_Detailverweis: <undefiniert>; U-Wert: 0.9; Schallschutzklasse: 35; Sonnenschutztyp: Movable
Fensteröffnung | H2 Ebene +2 | 1205Fen0000281201 | m² | 0 | Wärmedämm-Verbundsysteme | Fensteröffnung | 0 | 7.5 | NEW | 1205Wa 0000003096 | 0 | - | 0,51 | AllplanAttributes - ash D_Detailverweis: <undefiniert>; U-Wert: 0.9; Schallschutzklasse: 35; Sonnenschutztyp: Movable
Fensteröffnung | H2 Ebene +2 | 1205Fen0000281047 | m² | 0 | Wärmedämm-Verbundsysteme | Fensteröffnung | 0 | 7.5 | NEW | 1205Wa 0000003096 | 0 | - | 0,51 | AllplanAttributes - ash D_Detailverweis: <undefiniert>; U-Wert: 0.9; Schallschutzklasse: 35; Sonnenschutztyp: Movable
Fensteröffnung | H2 Ebene +2 | 1205Fen0000280395 | m² | 0 | Wärmedämm-Verbundsysteme | Fensteröffnung | 0 | 7.5 | NEW | 1205Wa 0000003092 | 0 | - | 0,51 | AllplanAttributes - ash D_Detailverweis: <undefiniert>; U-Wert: 0.9; Schallschutzklasse: 35; Sonnenschutztyp: Movable
Fensteröffnung | H2 Ebene +2 | 1205Fen0000280845 | m² | 0 | Wärmedämm-Verbundsysteme | Fensteröffnung | 0 | 7.5 | NEW | 1205Wa 0000003092 | 0 | - | 0,51 | AllplanAttributes - ash D_Detailverweis: <undefiniert>; U-Wert: 0.9; Schallschutzklasse: 35; Sonnenschutztyp: Movable
Fensteröffnung | H2 Ebene +2 | 1205Fen0000281155 | m² | 0 | Wärmedämm-Verbundsysteme | Fensteröffnung | 0 | 7.5 | NEW | 1205Wa 0000003088 | 0 | - | 0,51 | AllplanAttributes - ash D_Detailverweis: <undefiniert>; U-Wert: 0.9; Schallschutzklasse: 35; Sonnenschutztyp: Movable
Fensteröffnung | H2 Ebene +2 | 1205Fen0000280443 | m² | 0 | Wärmedämm-Verbundsysteme | Fensteröffnung | 0 | 7.5 | NEW | 1205Wa 0000003088 | 0 | - | 0,51 | AllplanAttributes - ash D_Detailverweis: <undefiniert>; U-Wert: 0.9; Schallschutzklasse: 35; Sonnenschutztyp: Movable
Fensteröffnung | H2 Ebene +2 | 1205Fen0000279965 | m² |  | Wärmedämm-Verbundsysteme | Fensteröffnung |  | 7.5 | NEW | 1205Wa 0000000332 | 0 | - | 0,51 | AllplanAttributes - Material: Fensterelement; Tragendes Bauteil: no; Brandabschnittsdefinierendes Bauteil: no; ash D_Detailverweis: <undefiniert>; U-Wert: 0.9; Schallschutzklasse: 32; Sonnenschutztyp: Movable
Fensteröffnung | H2 Ebene +2 | 1205Fen0000279974 | m² |  | Wärmedämm-Verbundsysteme | Fensteröffnung |  | 7.5 | NEW | 1205Wa 0000000332 | 0 | - | 0,51 | AllplanAttributes - Material: Fensterelement; Tragendes Bauteil: no; Brandabschnittsdefinierendes Bauteil: no; ash D_Detailverweis: <undefiniert>; U-Wert: 0.9; Schallschutzklasse: 32; Sonnenschutztyp: Movable
Fensteröffnung | H2 Ebene +2 | 1205Fen0000279982 | m³ | 0 | Wärmedämm-Verbundsysteme | Fensteröffnung | 0 | 7.5 | NEW | 1205Wa 0000000336 | 0 | - | 0,51 | AllplanAttributes - Material: Fensterelement; Außenliegend: yes; ash D_Detailverweis: <undefiniert>; U-Wert: 0.9; Schallschutzklasse: 32; Sonnenschutztyp: Movable
Fensteröffnung | H2 Ebene +2 | 1205Fen0000279996 | m³ | 0 | Wärmedämm-Verbundsysteme | Fensteröffnung | 0 | 7.5 | NEW | 1205Wa 0000000336 | 0 | - | 0,51 | AllplanAttributes - Material: Fensterelement; Außenliegend: yes; ash D_Detailverweis: <undefiniert>; U-Wert: 0.9; Schallschutzklasse: 32; Sonnenschutztyp: Movable
Fensteröffnung | H2 Ebene +2 | 1205Fen0000279984 | m³ | 0 | Wärmedämm-Verbundsysteme | Fensteröffnung | 0 | 7.5 | NEW | 1205Wa 0000000356 | 0 | - | 0,51 | AllplanAttributes - ash D_Detailverweis: <undefiniert>; U-Wert: 0.9; Schallschutzklasse: 32; Sonnenschutztyp: Movable
Fensteröffnung | H2 Ebene +2 | 1205Fen0000279986 | m³ | 0 | Wärmedämm-Verbundsysteme | Fensteröffnung | 0 | 7.5 | NEW | 1205Wa 0000000356 | 0 | - | 0,51 | AllplanAttributes - ash D_Detailverweis: <undefiniert>; U-Wert: 0.9; Schallschutzklasse: 32; Sonnenschutztyp: Movable
Fensteröffnung | H2 Ebene +2 | 1205Fen0000279957 | m² | 0 | Wärmedämm-Verbundsysteme | Fensteröffnung | 0 | 7.5 | NEW | 1205Wa 0000000352 | 0 | - | 0,51 | AllplanAttributes - ash D_Detailverweis: <undefiniert>; U-Wert: 0.9; Schallschutzklasse: 32; Sonnenschutztyp: Movable
Fensteröffnung | H2 Ebene +2 | 1205Fen0000279955 | m² | 0 | Wärmedämm-Verbundsysteme | Fensteröffnung | 0 | 7.5 | NEW | 1205Wa 0000000352 | 0 | - | 0,51 | AllplanAttributes - ash D_Detailverweis: <undefiniert>; U-Wert: 0.9; Schallschutzklasse: 32; Sonnenschutztyp: Movable
Fensteröffnung | H2 Ebene +2 | 1205Fen0000280573 | m² | 0 | Wärmedämm-Verbundsysteme | Fensteröffnung | 0 | 7.5 | NEW | 1205Wa 0000000348 | 0 | - | 0,51 | AllplanAttributes - ash D_Detailverweis: <undefiniert>; U-Wert: 0.9; Schallschutzklasse: 32; Sonnenschutztyp: Movable
Fensteröffnung | H2 Ebene +2 | 1205Fen0000280941 | m² | 0 | Wärmedämm-Verbundsysteme | Fensteröffnung | 0 | 7.5 | NEW | 1205Wa 0000000348 | 0 | - | 0,51 | AllplanAttributes - ash D_Detailverweis: <undefiniert>; U-Wert: 0.9; Schallschutzklasse: 32; Sonnenschutztyp: Movable
Fensteröffnung | H2 Ebene +2 | 1205Fen0000280937 | m² | 0 | Wärmedämm-Verbundsysteme | Fensteröffnung | 0 | 7.5 | NEW | 1205Wa 0000000344 | 0 | - | 0,51 | AllplanAttributes - ash D_Detailverweis: <undefiniert>; U-Wert: 0.9; Schallschutzklasse: 32; Sonnenschutztyp: Movable
Fensteröffnung | H2 Ebene +2 | 1205Fen0000280639 | m² | 0 | Wärmedämm-Verbundsysteme | Fensteröffnung | 0 | 7.5 | NEW | 1205Wa 0000000344 | 0 | - | 0,51 | AllplanAttributes - ash D_Detailverweis: <undefiniert>; U-Wert: 0.9; Schallschutzklasse: 32; Sonnenschutztyp: Movable
Fensteröffnung | H2 Ebene +2 | 1205Fen0000281205 | m² | 0 | Wärmedämm-Verbundsysteme | Fensteröffnung | 0 | 7.5 | NEW | 1205Wa 0000000340 | 0 | - | 0,51 | AllplanAttributes - ash D_Detailverweis: <undefiniert>; U-Wert: 0.9; Schallschutzklasse: 32; Sonnenschutztyp: Movable
Fensteröffnung | H2 Ebene +2 | 1205Fen0000280657 | m² | 0 | Wärmedämm-Verbundsysteme | Fensteröffnung | 0 | 7.5 | NEW | 1205Wa 0000000340 | 0 | - | 0,51 | AllplanAttributes - ash D_Detailverweis: <undefiniert>; U-Wert: 0.9; Schallschutzklasse: 32; Sonnenschutztyp: Movable
Fensteröffnung | H2 Ebene +2 | 1205Fen0000279971 | m² |  | Wärmedämm-Verbundsysteme | Fensteröffnung |  | 7.5 | NEW | 1205Wa 0000000388 | 0 | - | 0,51 | AllplanAttributes - Material: Fensterelement; Tragendes Bauteil: no; Brandabschnittsdefinierendes Bauteil: no; ash D_Detailverweis: <undefiniert>; U-Wert: 0.9; Schallschutzklasse: 32; Sonnenschutztyp: Movable
Fensteröffnung | H2 Ebene +2 | 1205Fen0000279977 | m² |  | Wärmedämm-Verbundsysteme | Fensteröffnung |  | 7.5 | NEW | 1205Wa 0000000388 | 0 | - | 0,51 | AllplanAttributes - Material: Fensterelement; Tragendes Bauteil: no; Brandabschnittsdefinierendes Bauteil: no; ash D_Detailverweis: <undefiniert>; U-Wert: 0.9; Schallschutzklasse: 32; Sonnenschutztyp: Movable
Fensteröffnung | H2 Ebene +2 | 1205Fen0000279992 | m³ | 0 | Wärmedämm-Verbundsysteme | Fensteröffnung | 0 | 7.5 | NEW | 1205Wa 0000000384 | 0 | - | 0,51 | AllplanAttributes - Material: Fensterelement; Außenliegend: yes; ash D_Detailverweis: <undefiniert>; U-Wert: 0.9; Schallschutzklasse: 32; Sonnenschutztyp: Movable
Fensteröffnung | H2 Ebene +2 | 1205Fen0000279988 | m³ | 0 | Wärmedämm-Verbundsysteme | Fensteröffnung | 0 | 7.5 | NEW | 1205Wa 0000000384 | 0 | - | 0,51 | AllplanAttributes - Material: Fensterelement; Außenliegend: yes; ash D_Detailverweis: <undefiniert>; U-Wert: 0.9; Schallschutzklasse: 32; Sonnenschutztyp: Movable
Fensteröffnung | H2 Ebene +2 | 1205Fen0000279994 | m³ | 0 | Wärmedämm-Verbundsysteme | Fensteröffnung | 0 | 7.5 | NEW | 1205Wa 0000000364 | 0 | - | 0,51 | AllplanAttributes - ash D_Detailverweis: <undefiniert>; U-Wert: 0.9; Schallschutzklasse: 32; Sonnenschutztyp: Movable
Fensteröffnung | H2 Ebene +2 | 1205Fen0000279998 | m³ | 0 | Wärmedämm-Verbundsysteme | Fensteröffnung | 0 | 7.5 | NEW | 1205Wa 0000000364 | 0 | - | 0,51 | AllplanAttributes - ash D_Detailverweis: <undefiniert>; U-Wert: 0.9; Schallschutzklasse: 32; Sonnenschutztyp: Movable
Fensteröffnung | H2 Ebene +2 | 1205Fen0000279961 | m² | 0 | Wärmedämm-Verbundsysteme | Fensteröffnung | 0 | 7.5 | NEW | 1205Wa 0000000368 | 0 | - | 0,51 | AllplanAttributes - ash D_Detailverweis: <undefiniert>; U-Wert: 0.9; Schallschutzklasse: 32; Sonnenschutztyp: Movable
Fensteröffnung | H2 Ebene +2 | 1205Fen0000279959 | m² | 0 | Wärmedämm-Verbundsysteme | Fensteröffnung | 0 | 7.5 | NEW | 1205Wa 0000000368 | 0 | - | 0,51 | AllplanAttributes - ash D_Detailverweis: <undefiniert>; U-Wert: 0.9; Schallschutzklasse: 32; Sonnenschutztyp: Movable
Fensteröffnung | H2 Ebene +2 | 1205Fen0000281125 | m² | 0 | Wärmedämm-Verbundsysteme | Fensteröffnung | 0 | 7.5 | NEW | 1205Wa 0000000372 | 0 | - | 0,51 | AllplanAttributes - ash D_Detailverweis: <undefiniert>; U-Wert: 0.9; Schallschutzklasse: 32; Sonnenschutztyp: Movable
Fensteröffnung | H2 Ebene +2 | 1205Fen0000280557 | m² | 0 | Wärmedämm-Verbundsysteme | Fensteröffnung | 0 | 7.5 | NEW | 1205Wa 0000000372 | 0 | - | 0,51 | AllplanAttributes - ash D_Detailverweis: <undefiniert>; U-Wert: 0.9; Schallschutzklasse: 32; Sonnenschutztyp: Movable
Fensteröffnung | H2 Ebene +2 | 1205Fen0000280441 | m² | 0 | Wärmedämm-Verbundsysteme | Fensteröffnung | 0 | 7.5 | NEW | 1205Wa 0000000376 | 0 | - | 0,51 | AllplanAttributes - ash D_Detailverweis: <undefiniert>; U-Wert: 0.9; Schallschutzklasse: 32; Sonnenschutztyp: Movable
Fensteröffnung | H2 Ebene +2 | 1205Fen0000280875 | m² | 0 | Wärmedämm-Verbundsysteme | Fensteröffnung | 0 | 7.5 | NEW | 1205Wa 0000000376 | 0 | - | 0,51 | AllplanAttributes - ash D_Detailverweis: <undefiniert>; U-Wert: 0.9; Schallschutzklasse: 32; Sonnenschutztyp: Movable
Fensteröffnung | H2 Ebene +2 | 1205Fen0000281093 | m² | 0 | Wärmedämm-Verbundsysteme | Fensteröffnung | 0 | 7.5 | NEW | 1205Wa 0000000380 | 0 | - | 0,51 | AllplanAttributes - ash D_Detailverweis: <undefiniert>; U-Wert: 0.9; Schallschutzklasse: 32; Sonnenschutztyp: Movable
Fensteröffnung | H2 Ebene +2 | 1205Fen0000280513 | m² | 0 | Wärmedämm-Verbundsysteme | Fensteröffnung | 0 | 7.5 | NEW | 1205Wa 0000000380 | 0 | - | 0,51 | AllplanAttributes - ash D_Detailverweis: <undefiniert>; U-Wert: 0.9; Schallschutzklasse: 32; Sonnenschutztyp: Movable
Fensteröffnung | H2 Ebene +2 | 1205Fen0000280217 | m² |  | Fensterarbeiten | Fensteröffnung |  | 7.5 |  | 1205Wa 0000002699 | 0 | - | 0,51 | AllplanAttributes - ash D_Detailverweis: <undefiniert>; U-Wert: 0.9; Schallschutzklasse: 32; Sonnenschutztyp: Movable
Fensteröffnung | H2 Ebene +2 | 1205Fen0000280235 | m² |  | Fensterarbeiten | Fensteröffnung |  | 7.5 |  | 1205Wa 0000002699 | 0 | - | 0,51 | AllplanAttributes - ash D_Detailverweis: <undefiniert>; U-Wert: 0.9; Schallschutzklasse: 32; Sonnenschutztyp: Movable
Fensteröffnung | H2 Ebene +2 | 1205Fen0000280118 | m² |  | Fensterarbeiten | Fensteröffnung |  | 7.5 |  | 1205Wa 0000002699 | 0 | - | 0,51 | AllplanAttributes - ash D_Detailverweis: <undefiniert>; U-Wert: 0.9; Schallschutzklasse: 32; Sonnenschutztyp: Movable
Fensteröffnung | H2 Ebene +2 | 1205Fen0000280277 | m² |  | Fensterarbeiten | Fensteröffnung |  | 7.5 |  | 1205Wa 0000002699 | 0 | - | 0,51 | AllplanAttributes - ash D_Detailverweis: <undefiniert>; U-Wert: 0.9; Schallschutzklasse: 32; Sonnenschutztyp: Movable
Fensteröffnung | H2 Ebene +2 | 1205Fen0000280833 | m³ | 0 | Fensterarbeiten | Fensteröffnung | 0 | 7.5 |  | 1205Wa 0000002706 | 0 | - | 0,51 | AllplanAttributes - ash D_Detailverweis: <undefiniert>; U-Wert: 0.9; Schallschutzklasse: 32; Sonnenschutztyp: Movable
Fensteröffnung | H2 Ebene +2 | 1205Fen0000281165 | m³ | 0 | Fensterarbeiten | Fensteröffnung | 0 | 7.5 |  | 1205Wa 0000002706 | 0 | - | 0,51 | AllplanAttributes - ash D_Detailverweis: <undefiniert>; U-Wert: 0.9; Schallschutzklasse: 32; Sonnenschutztyp: Movable
Fensteröffnung | H2 Ebene +2 | 1205Fen0000280473 | m³ | 0 | Fensterarbeiten | Fensteröffnung | 0 | 7.5 |  | 1205Wa 0000002706 | 0 | - | 0,51 | AllplanAttributes - ash D_Detailverweis: <undefiniert>; U-Wert: 0.9; Schallschutzklasse: 32; Sonnenschutztyp: Movable
Fensteröffnung | H2 Ebene +2 | 1205Fen0000281005 | m³ | 0 | Fensterarbeiten | Fensteröffnung | 0 | 7.5 |  | 1205Wa 0000002706 | 0 | - | 0,51 | AllplanAttributes - ash D_Detailverweis: <undefiniert>; U-Wert: 0.9; Schallschutzklasse: 32; Sonnenschutztyp: Movable
Fensteröffnung | H2 Ebene +2 | 1205Fen0000280703 | m³ | 0 | Fensterarbeiten | Fensteröffnung | 0 | 7.5 |  | 1205Wa 0000002713 | 0 | - | 0,51 | AllplanAttributes - ash D_Detailverweis: <undefiniert>; U-Wert: 0.9; Schallschutzklasse: 32; Sonnenschutztyp: Movable
Fensteröffnung | H2 Ebene +2 | 1205Fen0000280851 | m³ | 0 | Fensterarbeiten | Fensteröffnung | 0 | 7.5 |  | 1205Wa 0000002713 | 0 | - | 0,51 | AllplanAttributes - ash D_Detailverweis: <undefiniert>; U-Wert: 0.9; Schallschutzklasse: 32; Sonnenschutztyp: Movable
Fensteröffnung | H2 Ebene +2 | 1205Fen0000280663 | m³ | 0 | Fensterarbeiten | Fensteröffnung | 0 | 7.5 |  | 1205Wa 0000002713 | 0 | - | 0,51 | AllplanAttributes - ash D_Detailverweis: <undefiniert>; U-Wert: 0.9; Schallschutzklasse: 32; Sonnenschutztyp: Movable
Fensteröffnung | H2 Ebene +2 | 1205Fen0000280957 | m³ | 0 | Fensterarbeiten | Fensteröffnung | 0 | 7.5 |  | 1205Wa 0000002713 | 0 | - | 0,51 | AllplanAttributes - ash D_Detailverweis: <undefiniert>; U-Wert: 0.9; Schallschutzklasse: 32; Sonnenschutztyp: Movable
Fensteröffnung | H2 Ebene +2 | 1205Fen0000280415 | m² | 0 | Fensterarbeiten | Fensteröffnung | 0 | 7.5 |  | 1205Wa 0000002720 | 0 | - | 0,51 | AllplanAttributes - ash D_Detailverweis: <undefiniert>; U-Wert: 0.9; Schallschutzklasse: 32; Sonnenschutztyp: Movable
Fensteröffnung | H2 Ebene +2 | 1205Fen0000281043 | m² | 0 | Fensterarbeiten | Fensteröffnung | 0 | 7.5 |  | 1205Wa 0000002720 | 0 | - | 0,51 | AllplanAttributes - ash D_Detailverweis: <undefiniert>; U-Wert: 0.9; Schallschutzklasse: 32; Sonnenschutztyp: Movable
Fensteröffnung | H2 Ebene +2 | 1205Fen0000280701 | m² | 0 | Fensterarbeiten | Fensteröffnung | 0 | 7.5 |  | 1205Wa 0000002720 | 0 | - | 0,51 | AllplanAttributes - ash D_Detailverweis: <undefiniert>; U-Wert: 0.9; Schallschutzklasse: 32; Sonnenschutztyp: Movable
Fensteröffnung | H2 Ebene +2 | 1205Fen0000281091 | m² | 0 | Fensterarbeiten | Fensteröffnung | 0 | 7.5 |  | 1205Wa 0000002720 | 0 | - | 0,51 | AllplanAttributes - ash D_Detailverweis: <undefiniert>; U-Wert: 0.9; Schallschutzklasse: 32; Sonnenschutztyp: Movable
Fensteröffnung | H2 Ebene +2 | 1205Fen0000280857 | m² | 0 | Fensterarbeiten | Fensteröffnung | 0 | 7.5 | NEW | 1205Wa 0000002727 | 0 | - | 0,51 | AllplanAttributes - ash D_Detailverweis: <undefiniert>; U-Wert: 0.9; Schallschutzklasse: 32; Sonnenschutztyp: Movable
Fensteröffnung | H2 Ebene +2 | 1205Fen0000280677 | m² | 0 | Fensterarbeiten | Fensteröffnung | 0 | 7.5 | NEW | 1205Wa 0000002727 | 0 | - | 0,51 | AllplanAttributes - ash D_Detailverweis: <undefiniert>; U-Wert: 0.9; Schallschutzklasse: 32; Sonnenschutztyp: Movable
Fensteröffnung | H2 Ebene +2 | 1205Fen0000280405 | m² | 0 | Fensterarbeiten | Fensteröffnung | 0 | 7.5 | NEW | 1205Wa 0000002727 | 0 | - | 0,51 | AllplanAttributes - ash D_Detailverweis: <undefiniert>; U-Wert: 0.9; Schallschutzklasse: 32; Sonnenschutztyp: Movable
Fensteröffnung | H2 Ebene +2 | 1205Fen0000280695 | m² | 0 | Fensterarbeiten | Fensteröffnung | 0 | 7.5 | NEW | 1205Wa 0000002727 | 0 | - | 0,51 | AllplanAttributes - ash D_Detailverweis: <undefiniert>; U-Wert: 0.9; Schallschutzklasse: 32; Sonnenschutztyp: Movable
Fensteröffnung | H2 Ebene +2 | 1205Fen0000280511 | m² | 0 | Fensterarbeiten | Fensteröffnung | 0 | 7.5 | NEW | 1205Wa 0000002734 | 0 | - | 0,51 | AllplanAttributes - ash D_Detailverweis: <undefiniert>; U-Wert: 0.9; Schallschutzklasse: 32; Sonnenschutztyp: Movable
Fensteröffnung | H2 Ebene +2 | 1205Fen0000280411 | m² | 0 | Fensterarbeiten | Fensteröffnung | 0 | 7.5 | NEW | 1205Wa 0000002734 | 0 | - | 0,51 | AllplanAttributes - ash D_Detailverweis: <undefiniert>; U-Wert: 0.9; Schallschutzklasse: 32; Sonnenschutztyp: Movable
Fensteröffnung | H2 Ebene +2 | 1205Fen0000280547 | m² | 0 | Fensterarbeiten | Fensteröffnung | 0 | 7.5 | NEW | 1205Wa 0000002734 | 0 | - | 0,51 | AllplanAttributes - ash D_Detailverweis: <undefiniert>; U-Wert: 0.9; Schallschutzklasse: 32; Sonnenschutztyp: Movable
Fensteröffnung | H2 Ebene +2 | 1205Fen0000281199 | m² | 0 | Fensterarbeiten | Fensteröffnung | 0 | 7.5 | NEW | 1205Wa 0000002734 | 0 | - | 0,51 | AllplanAttributes - ash D_Detailverweis: <undefiniert>; U-Wert: 0.9; Schallschutzklasse: 32; Sonnenschutztyp: Movable
Fensteröffnung | H2 Ebene +2 | 1205Fen0000280433 | m² | 0 | Fensterarbeiten | Fensteröffnung | 0 | 7.5 | NEW | 1205Wa 0000002741 | 0 | - | 0,51 | AllplanAttributes - ash D_Detailverweis: <undefiniert>; U-Wert: 0.9; Schallschutzklasse: 32; Sonnenschutztyp: Movable
Fensteröffnung | H2 Ebene +2 | 1205Fen0000280803 | m² | 0 | Fensterarbeiten | Fensteröffnung | 0 | 7.5 | NEW | 1205Wa 0000002741 | 0 | - | 0,51 | AllplanAttributes - ash D_Detailverweis: <undefiniert>; U-Wert: 0.9; Schallschutzklasse: 32; Sonnenschutztyp: Movable
Fensteröffnung | H2 Ebene +2 | 1205Fen0000280581 | m² | 0 | Fensterarbeiten | Fensteröffnung | 0 | 7.5 | NEW | 1205Wa 0000002741 | 0 | - | 0,51 | AllplanAttributes - ash D_Detailverweis: <undefiniert>; U-Wert: 0.9; Schallschutzklasse: 32; Sonnenschutztyp: Movable
Fensteröffnung | H2 Ebene +2 | 1205Fen0000280933 | m² | 0 | Fensterarbeiten | Fensteröffnung | 0 | 7.5 | NEW | 1205Wa 0000002741 | 0 | - | 0,51 | AllplanAttributes - ash D_Detailverweis: <undefiniert>; U-Wert: 0.9; Schallschutzklasse: 32; Sonnenschutztyp: Movable
Fensteröffnung | H2 Ebene +2 | 1205Fen0000280181 | m² |  | Wärmedämm-Verbundsysteme | Fensteröffnung |  | 7.5 | NEW | 1205Wa 0000000910 | 0 | - | 0,51 | AllplanAttributes - Material: Fensterelement; Tragendes Bauteil: no; Brandabschnittsdefinierendes Bauteil: no; ash D_Detailverweis: <undefiniert>; U-Wert: 0.9; Schallschutzklasse: 32; Sonnenschutztyp: Movable
Fensteröffnung | H2 Ebene +2 | 1205Fen0000280124 | m² |  | Wärmedämm-Verbundsysteme | Fensteröffnung |  | 7.5 | NEW | 1205Wa 0000000910 | 0 | - | 0,51 | AllplanAttributes - Material: Fensterelement; Tragendes Bauteil: no; Brandabschnittsdefinierendes Bauteil: no; ash D_Detailverweis: <undefiniert>; U-Wert: 0.9; Schallschutzklasse: 32; Sonnenschutztyp: Movable
Fensteröffnung | H2 Ebene +2 | 1205Fen0000280603 | m³ | 0 | Wärmedämm-Verbundsysteme | Fensteröffnung | 0 | 7.5 | NEW | 1205Wa 0000000914 | 0 | - | 0,51 | AllplanAttributes - Material: Fensterelement; Außenliegend: yes; ash D_Detailverweis: <undefiniert>; U-Wert: 0.9; Schallschutzklasse: 32; Sonnenschutztyp: Movable
Fensteröffnung | H2 Ebene +2 | 1205Fen0000280955 | m³ | 0 | Wärmedämm-Verbundsysteme | Fensteröffnung | 0 | 7.5 | NEW | 1205Wa 0000000914 | 0 | - | 0,51 | AllplanAttributes - Material: Fensterelement; Außenliegend: yes; ash D_Detailverweis: <undefiniert>; U-Wert: 0.9; Schallschutzklasse: 32; Sonnenschutztyp: Movable
Fensteröffnung | H2 Ebene +2 | 1205Fen0000280693 | m³ | 0 | Wärmedämm-Verbundsysteme | Fensteröffnung | 0 | 7.5 | NEW | 1205Wa 0000000934 | 0 | - | 0,51 | AllplanAttributes - ash D_Detailverweis: <undefiniert>; U-Wert: 0.9; Schallschutzklasse: 32; Sonnenschutztyp: Movable
Fensteröffnung | H2 Ebene +2 | 1205Fen0000281187 | m³ | 0 | Wärmedämm-Verbundsysteme | Fensteröffnung | 0 | 7.5 | NEW | 1205Wa 0000000934 | 0 | - | 0,51 | AllplanAttributes - ash D_Detailverweis: <undefiniert>; U-Wert: 0.9; Schallschutzklasse: 32; Sonnenschutztyp: Movable
Fensteröffnung | H2 Ebene +2 | 1205Fen0000280477 | m² | 0 | Wärmedämm-Verbundsysteme | Fensteröffnung | 0 | 7.5 | NEW | 1205Wa 0000000930 | 0 | - | 0,51 | AllplanAttributes - ash D_Detailverweis: <undefiniert>; U-Wert: 0.9; Schallschutzklasse: 32; Sonnenschutztyp: Movable
Fensteröffnung | H2 Ebene +2 | 1205Fen0000281063 | m² | 0 | Wärmedämm-Verbundsysteme | Fensteröffnung | 0 | 7.5 | NEW | 1205Wa 0000000930 | 0 | - | 0,51 | AllplanAttributes - ash D_Detailverweis: <undefiniert>; U-Wert: 0.9; Schallschutzklasse: 32; Sonnenschutztyp: Movable
Fensteröffnung | H2 Ebene +2 | 1205Fen0000280819 | m² | 0 | Wärmedämm-Verbundsysteme | Fensteröffnung | 0 | 7.5 | NEW | 1205Wa 0000000926 | 0 | - | 0,51 | AllplanAttributes - ash D_Detailverweis: <undefiniert>; U-Wert: 0.9; Schallschutzklasse: 32; Sonnenschutztyp: Movable
Fensteröffnung | H2 Ebene +2 | 1205Fen0000280681 | m² | 0 | Wärmedämm-Verbundsysteme | Fensteröffnung | 0 | 7.5 | NEW | 1205Wa 0000000926 | 0 | - | 0,51 | AllplanAttributes - ash D_Detailverweis: <undefiniert>; U-Wert: 0.9; Schallschutzklasse: 32; Sonnenschutztyp: Movable
Fensteröffnung | H2 Ebene +2 | 1205Fen0000281171 | m² | 0 | Wärmedämm-Verbundsysteme | Fensteröffnung | 0 | 7.5 | NEW | 1205Wa 0000000922 | 0 | - | 0,51 | AllplanAttributes - ash D_Detailverweis: <undefiniert>; U-Wert: 0.9; Schallschutzklasse: 32; Sonnenschutztyp: Movable
Fensteröffnung | H2 Ebene +2 | 1205Fen0000281211 | m² | 0 | Wärmedämm-Verbundsysteme | Fensteröffnung | 0 | 7.5 | NEW | 1205Wa 0000000922 | 0 | - | 0,51 | AllplanAttributes - ash D_Detailverweis: <undefiniert>; U-Wert: 0.9; Schallschutzklasse: 32; Sonnenschutztyp: Movable
Fensteröffnung | H2 Ebene +2 | 1205Fen0000280963 | m² | 0 | Wärmedämm-Verbundsysteme | Fensteröffnung | 0 | 7.5 | NEW | 1205Wa 0000000918 | 0 | - | 0,51 | AllplanAttributes - ash D_Detailverweis: <undefiniert>; U-Wert: 0.9; Schallschutzklasse: 32; Sonnenschutztyp: Movable
Fensteröffnung | H2 Ebene +2 | 1205Fen0000280469 | m² | 0 | Wärmedämm-Verbundsysteme | Fensteröffnung | 0 | 7.5 | NEW | 1205Wa 0000000918 | 0 | - | 0,51 | AllplanAttributes - ash D_Detailverweis: <undefiniert>; U-Wert: 0.9; Schallschutzklasse: 32; Sonnenschutztyp: Movable
Fensteröffnung | H2 Ebene +2 | 1205Fen0000280310 | m² |  | Wärmedämm-Verbundsysteme | Fensteröffnung |  | 7.5 | NEW | 1205Wa 0000002807 | 0 | - | 0,51 | AllplanAttributes - Material: Fensterelement; Tragendes Bauteil: no; Brandabschnittsdefinierendes Bauteil: no; ash D_Detailverweis: <undefiniert>; U-Wert: 0.9; Schallschutzklasse: 32; Sonnenschutztyp: Movable
Fensteröffnung | H2 Ebene +2 | 1205Fen0000280232 | m² |  | Wärmedämm-Verbundsysteme | Fensteröffnung |  | 7.5 | NEW | 1205Wa 0000002807 | 0 | - | 0,51 | AllplanAttributes - Material: Fensterelement; Tragendes Bauteil: no; Brandabschnittsdefinierendes Bauteil: no; ash D_Detailverweis: <undefiniert>; U-Wert: 0.9; Schallschutzklasse: 32; Sonnenschutztyp: Movable
Fensteröffnung | H2 Ebene +2 | 1205Fen0000281175 | m³ | 0 | Wärmedämm-Verbundsysteme | Fensteröffnung | 0 | 7.5 | NEW | 1205Wa 0000002803 | 0 | - | 0,51 | AllplanAttributes - Material: Fensterelement; Außenliegend: yes; ash D_Detailverweis: <undefiniert>; U-Wert: 0.9; Schallschutzklasse: 32; Sonnenschutztyp: Movable
Fensteröffnung | H2 Ebene +2 | 1205Fen0000280809 | m³ | 0 | Wärmedämm-Verbundsysteme | Fensteröffnung | 0 | 7.5 | NEW | 1205Wa 0000002803 | 0 | - | 0,51 | AllplanAttributes - Material: Fensterelement; Außenliegend: yes; ash D_Detailverweis: <undefiniert>; U-Wert: 0.9; Schallschutzklasse: 32; Sonnenschutztyp: Movable
Fensteröffnung | H2 Ebene +2 | 1205Fen0000280491 | m³ | 0 | Wärmedämm-Verbundsysteme | Fensteröffnung | 0 | 7.5 | NEW | 1205Wa 0000002799 | 0 | - | 0,51 | AllplanAttributes - ash D_Detailverweis: <undefiniert>; U-Wert: 0.9; Schallschutzklasse: 32; Sonnenschutztyp: Movable
Fensteröffnung | H2 Ebene +2 | 1205Fen0000280945 | m³ | 0 | Wärmedämm-Verbundsysteme | Fensteröffnung | 0 | 7.5 | NEW | 1205Wa 0000002799 | 0 | - | 0,51 | AllplanAttributes - ash D_Detailverweis: <undefiniert>; U-Wert: 0.9; Schallschutzklasse: 32; Sonnenschutztyp: Movable
Fensteröffnung | H2 Ebene +2 | 1205Fen0000281007 | m² | 0 | Wärmedämm-Verbundsysteme | Fensteröffnung | 0 | 7.5 | NEW | 1205Wa 0000002795 | 0 | - | 0,51 | AllplanAttributes - ash D_Detailverweis: <undefiniert>; U-Wert: 0.9; Schallschutzklasse: 32; Sonnenschutztyp: Movable
Fensteröffnung | H2 Ebene +2 | 1205Fen0000280553 | m² | 0 | Wärmedämm-Verbundsysteme | Fensteröffnung | 0 | 7.5 | NEW | 1205Wa 0000002795 | 0 | - | 0,51 | AllplanAttributes - ash D_Detailverweis: <undefiniert>; U-Wert: 0.9; Schallschutzklasse: 32; Sonnenschutztyp: Movable
Fensteröffnung | H2 Ebene +2 | 1205Fen0000280527 | m² | 0 | Wärmedämm-Verbundsysteme | Fensteröffnung | 0 | 7.5 | NEW | 1205Wa 0000002791 | 0 | - | 0,51 | AllplanAttributes - ash D_Detailverweis: <undefiniert>; U-Wert: 0.9; Schallschutzklasse: 32; Sonnenschutztyp: Movable
Fensteröffnung | H2 Ebene +2 | 1205Fen0000280445 | m² | 0 | Wärmedämm-Verbundsysteme | Fensteröffnung | 0 | 7.5 | NEW | 1205Wa 0000002791 | 0 | - | 0,51 | AllplanAttributes - ash D_Detailverweis: <undefiniert>; U-Wert: 0.9; Schallschutzklasse: 32; Sonnenschutztyp: Movable
Fensteröffnung | H2 Ebene +2 | 1205Fen0000280653 | m² | 0 | Wärmedämm-Verbundsysteme | Fensteröffnung | 0 | 7.5 | NEW | 1205Wa 0000002787 | 0 | - | 0,51 | AllplanAttributes - ash D_Detailverweis: <undefiniert>; U-Wert: 0.9; Schallschutzklasse: 32; Sonnenschutztyp: Movable
Fensteröffnung | H2 Ebene +2 | 1205Fen0000281009 | m² | 0 | Wärmedämm-Verbundsysteme | Fensteröffnung | 0 | 7.5 | NEW | 1205Wa 0000002787 | 0 | - | 0,51 | AllplanAttributes - ash D_Detailverweis: <undefiniert>; U-Wert: 0.9; Schallschutzklasse: 32; Sonnenschutztyp: Movable
Fensteröffnung | H2 Ebene +2 | 1205Fen0000280599 | m² | 0 | Wärmedämm-Verbundsysteme | Fensteröffnung | 0 | 7.5 | NEW | 1205Wa 0000002783 | 0 | - | 0,51 | AllplanAttributes - ash D_Detailverweis: <undefiniert>; U-Wert: 0.9; Schallschutzklasse: 32; Sonnenschutztyp: Movable
Fensteröffnung | H2 Ebene +2 | 1205Fen0000280627 | m² | 0 | Wärmedämm-Verbundsysteme | Fensteröffnung | 0 | 7.5 | NEW | 1205Wa 0000002783 | 0 | - | 0,51 | AllplanAttributes - ash D_Detailverweis: <undefiniert>; U-Wert: 0.9; Schallschutzklasse: 32; Sonnenschutztyp: Movable
Fensteröffnung | H2 Ebene +2 | 1205Fen0000280229 | m² |  | Fensterarbeiten | Fensteröffnung |  | 7.5 |  | 1205Wa 0000002907 | 0 | - | 0,51 | AllplanAttributes - ash D_Detailverweis: <undefiniert>; U-Wert: 0.9; Schallschutzklasse: 32; Sonnenschutztyp: Movable
Fensteröffnung | H2 Ebene +2 | 1205Fen0000280919 | m³ | 0 | Fensterarbeiten | Fensteröffnung | 0 | 7.5 |  | 1205Wa 0000002903 | 0 | - | 0,51 | AllplanAttributes - ash D_Detailverweis: <undefiniert>; U-Wert: 0.9; Schallschutzklasse: 32; Sonnenschutztyp: Movable
Fensteröffnung | H2 Ebene +2 | 1205Fen0000280911 | m³ | 0 | Fensterarbeiten | Fensteröffnung | 0 | 7.5 |  | 1205Wa 0000002899 | 0 | - | 0,51 | AllplanAttributes - ash D_Detailverweis: <undefiniert>; U-Wert: 0.9; Schallschutzklasse: 32; Sonnenschutztyp: Movable
Fensteröffnung | H2 Ebene +2 | 1205Fen0000280595 | m² | 0 | Fensterarbeiten | Fensteröffnung | 0 | 7.5 |  | 1205Wa 0000002895 | 0 | - | 0,51 | AllplanAttributes - ash D_Detailverweis: <undefiniert>; U-Wert: 0.9; Schallschutzklasse: 32; Sonnenschutztyp: Movable
Fensteröffnung | H2 Ebene +2 | 1205Fen0000281017 | m² | 0 | Fensterarbeiten | Fensteröffnung | 0 | 7.5 | NEW | 1205Wa 0000002891 | 0 | - | 0,51 | AllplanAttributes - ash D_Detailverweis: <undefiniert>; U-Wert: 0.9; Schallschutzklasse: 32; Sonnenschutztyp: Movable
Fensteröffnung | H2 Ebene +2 | 1205Fen0000280611 | m² | 0 | Fensterarbeiten | Fensteröffnung | 0 | 7.5 | NEW | 1205Wa 0000002887 | 0 | - | 0,51 | AllplanAttributes - ash D_Detailverweis: <undefiniert>; U-Wert: 0.9; Schallschutzklasse: 32; Sonnenschutztyp: Movable
Fensteröffnung | H2 Ebene +2 | 1205Fen0000280921 | m² | 0 | Fensterarbeiten | Fensteröffnung | 0 | 7.5 | NEW | 1205Wa 0000002883 | 0 | - | 0,51 | AllplanAttributes - ash D_Detailverweis: <undefiniert>; U-Wert: 0.9; Schallschutzklasse: 32; Sonnenschutztyp: Movable
Fensteröffnung | H2 Ebene +2 | 1205Fen0000281293 | m² |  | Fensterarbeiten | Fensteröffnung |  | 7.5 |  | 1205Wa 0000003057 | 0 | - | 0,51 | AllplanAttributes - ash D_Detailverweis: <undefiniert>; U-Wert: 0.9; Schallschutzklasse: 32; Sonnenschutztyp: Movable
Fensteröffnung | H2 Ebene +2 | 1205Fen0000281297 | m³ | 0 | Fensterarbeiten | Fensteröffnung | 0 | 7.5 |  | 1205Wa 0000003053 | 0 | - | 0,51 | AllplanAttributes - ash D_Detailverweis: <undefiniert>; U-Wert: 0.9; Schallschutzklasse: 32; Sonnenschutztyp: Movable
Fensteröffnung | H2 Ebene +2 | 1205Fen0000281301 | m³ | 0 | Fensterarbeiten | Fensteröffnung | 0 | 7.5 |  | 1205Wa 0000003049 | 0 | - | 0,51 | AllplanAttributes - ash D_Detailverweis: <undefiniert>; U-Wert: 0.9; Schallschutzklasse: 32; Sonnenschutztyp: Movable
Fensteröffnung | H2 Ebene +2 | 1205Fen0000281259 | m² | 0 | Fensterarbeiten | Fensteröffnung | 0 | 7.5 |  | 1205Wa 0000003045 | 0 | - | 0,51 | AllplanAttributes - ash D_Detailverweis: <undefiniert>; U-Wert: 0.9; Schallschutzklasse: 32; Sonnenschutztyp: Movable
Fensteröffnung | H2 Ebene +2 | 1205Fen0000281255 | m² | 0 | Fensterarbeiten | Fensteröffnung | 0 | 7.5 | NEW | 1205Wa 0000003041 | 0 | - | 0,51 | AllplanAttributes - ash D_Detailverweis: <undefiniert>; U-Wert: 0.9; Schallschutzklasse: 32; Sonnenschutztyp: Movable
Fensteröffnung | H2 Ebene +2 | 1205Fen0000281237 | m² | 0 | Fensterarbeiten | Fensteröffnung | 0 | 7.5 | NEW | 1205Wa 0000003037 | 0 | - | 0,51 | AllplanAttributes - ash D_Detailverweis: <undefiniert>; U-Wert: 0.9; Schallschutzklasse: 32; Sonnenschutztyp: Movable
Fensteröffnung | H2 Ebene +2 | 1205Fen0000281271 | m² | 0 | Fensterarbeiten | Fensteröffnung | 0 | 7.5 | NEW | 1205Wa 0000003033 | 0 | - | 0,51 | AllplanAttributes - ash D_Detailverweis: <undefiniert>; U-Wert: 0.9; Schallschutzklasse: 32; Sonnenschutztyp: Movable
Fensteröffnung | H2 Ebene +2 | 1205Fen0000280280 | m² | 0 | Fensterarbeiten | Fensteröffnung | 0 | 7.5 |  | 1205Wa 0000003947 | 0 | - | 0,51 | AllplanAttributes - ash D_Detailverweis: <undefiniert>; U-Wert: 0.9; Schallschutzklasse: 32; Sonnenschutztyp: Movable
Fensteröffnung | H2 Ebene +2 | 1205Fen0000280199 | m² | 0 | Fensterarbeiten | Fensteröffnung | 0 | 7.5 |  | 1205Wa 0000003947 | 0 | - | 0,51 | AllplanAttributes - ash D_Detailverweis: <undefiniert>; U-Wert: 0.9; Schallschutzklasse: 32; Sonnenschutztyp: Movable
Fensteröffnung | H2 Ebene +2 | 1205Fen0000280211 | m² | 0 | Fensterarbeiten | Fensteröffnung | 0 | 7.5 |  | 1205Wa 0000003947 | 0 | - | 0,51 | AllplanAttributes - ash D_Detailverweis: <undefiniert>; U-Wert: 0.9; Schallschutzklasse: 32; Sonnenschutztyp: Movable
Fensteröffnung | H2 Ebene +2 | 1205Fen0000280133 | m² | 0 | Fensterarbeiten | Fensteröffnung | 0 | 7.5 |  | 1205Wa 0000003947 | 0 | - | 0,51 | AllplanAttributes - ash D_Detailverweis: <undefiniert>; U-Wert: 0.9; Schallschutzklasse: 32; Sonnenschutztyp: Movable
Fensteröffnung | H2 Ebene +2 | 1205Fen0000344919 | m² | 0 | Fensterarbeiten | Fensteröffnung | 0 | 7.5 |  | 1205Wa 0000003947 | 0 | - | 0,51 | AllplanAttributes - ash D_Detailverweis: <undefiniert>; U-Wert: 0.9; Schallschutzklasse: 32; Sonnenschutztyp: Movable
Fensteröffnung | H2 Ebene +2 | 1205Fen0000280915 | m³ | 0 | Fensterarbeiten | Fensteröffnung | 0 | 7.5 |  | 1205Wa 0000003957 | 0 | - | 0,51 | AllplanAttributes - ash D_Detailverweis: <undefiniert>; U-Wert: 0.9; Schallschutzklasse: 32; Sonnenschutztyp: Movable
Fensteröffnung | H2 Ebene +2 | 1205Fen0000280877 | m³ | 0 | Fensterarbeiten | Fensteröffnung | 0 | 7.5 |  | 1205Wa 0000003957 | 0 | - | 0,51 | AllplanAttributes - ash D_Detailverweis: <undefiniert>; U-Wert: 0.9; Schallschutzklasse: 32; Sonnenschutztyp: Movable
Fensteröffnung | H2 Ebene +2 | 1205Fen0000344918 | m³ | 0 | Fensterarbeiten | Fensteröffnung | 0 | 7.5 |  | 1205Wa 0000003957 | 0 | - | 0,51 | AllplanAttributes - ash D_Detailverweis: <undefiniert>; U-Wert: 0.9; Schallschutzklasse: 32; Sonnenschutztyp: Movable
Fensteröffnung | H2 Ebene +2 | 1205Fen0000280717 | m³ | 0 | Fensterarbeiten | Fensteröffnung | 0 | 7.5 |  | 1205Wa 0000003957 | 0 | - | 0,51 | AllplanAttributes - ash D_Detailverweis: <undefiniert>; U-Wert: 0.9; Schallschutzklasse: 32; Sonnenschutztyp: Movable
Fensteröffnung | H2 Ebene +2 | 1205Fen0000280705 | m³ | 0 | Fensterarbeiten | Fensteröffnung | 0 | 7.5 |  | 1205Wa 0000003957 | 0 | - | 0,51 | AllplanAttributes - ash D_Detailverweis: <undefiniert>; U-Wert: 0.9; Schallschutzklasse: 32; Sonnenschutztyp: Movable
Fensteröffnung | H2 Ebene +2 | 1205Fen0000280463 | m³ | 0 | Fensterarbeiten | Fensteröffnung | 0 | 7.5 |  | 1205Wa 0000003966 | 0 | - | 0,51 | AllplanAttributes - ash D_Detailverweis: <undefiniert>; U-Wert: 0.9; Schallschutzklasse: 32; Sonnenschutztyp: Movable
Fensteröffnung | H2 Ebene +2 | 1205Fen0000280973 | m³ | 0 | Fensterarbeiten | Fensteröffnung | 0 | 7.5 |  | 1205Wa 0000003966 | 0 | - | 0,51 | AllplanAttributes - ash D_Detailverweis: <undefiniert>; U-Wert: 0.9; Schallschutzklasse: 32; Sonnenschutztyp: Movable
Fensteröffnung | H2 Ebene +2 | 1205Fen0000344917 | m³ | 0 | Fensterarbeiten | Fensteröffnung | 0 | 7.5 |  | 1205Wa 0000003966 | 0 | - | 0,51 | AllplanAttributes - ash D_Detailverweis: <undefiniert>; U-Wert: 0.9; Schallschutzklasse: 32; Sonnenschutztyp: Movable
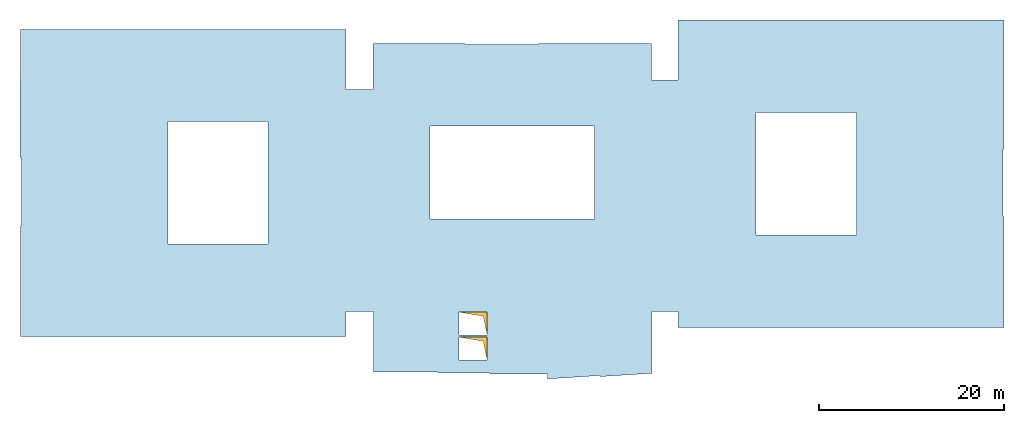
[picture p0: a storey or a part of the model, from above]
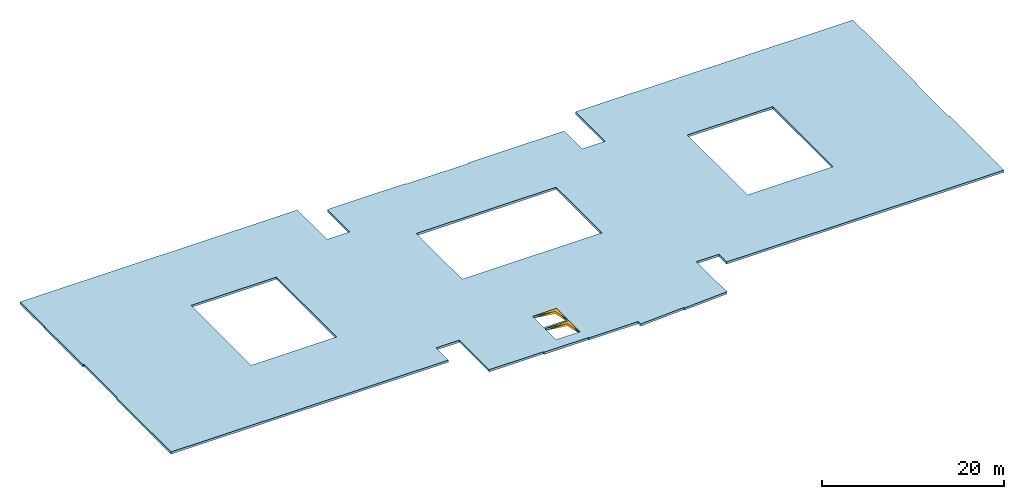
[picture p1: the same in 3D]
Properties of the parts of a building model (IFC4), part 31 of 80

# IfcOpeningElement: Opening (3497)
Name | In | Allright_Bauteil_ID | Abrechnungsart | Versatz_oben | Gewerk | Objektname | Versatz_unten | OKFF | Status | P_ID | AllplanAttributes, Feuerwiderstandsklasse | Sicherheitsklasse | g-Wert
Fensteröffnung | H2 Ebene +2 | 1205Fen0000280733 | m³ | 0 | Fensterarbeiten | Fensteröffnung | 0 | 7.5 |  | 1205Wa 0000003966 | 0 | - | 0,51 | AllplanAttributes - ash D_Detailverweis: <undefiniert>; U-Wert: 0.9; Schallschutzklasse: 32; Sonnenschutztyp: Movable
Fensteröffnung | H2 Ebene +2 | 1205Fen0000280505 | m³ | 0 | Fensterarbeiten | Fensteröffnung | 0 | 7.5 |  | 1205Wa 0000003966 | 0 | - | 0,51 | AllplanAttributes - ash D_Detailverweis: <undefiniert>; U-Wert: 0.9; Schallschutzklasse: 32; Sonnenschutztyp: Movable
Fensteröffnung | H2 Ebene +2 | 1205Fen0000281029 | m² | 0 | Fensterarbeiten | Fensteröffnung | 0 | 7.5 |  | 1205Wa 0000003976 | 0 | - | 0,51 | AllplanAttributes - ash D_Detailverweis: <undefiniert>; U-Wert: 0.9; Schallschutzklasse: 32; Sonnenschutztyp: Movable
Fensteröffnung | H2 Ebene +2 | 1205Fen0000280523 | m² | 0 | Fensterarbeiten | Fensteröffnung | 0 | 7.5 |  | 1205Wa 0000003976 | 0 | - | 0,51 | AllplanAttributes - ash D_Detailverweis: <undefiniert>; U-Wert: 0.9; Schallschutzklasse: 32; Sonnenschutztyp: Movable
Fensteröffnung | H2 Ebene +2 | 1205Fen0000344916 | m² | 0 | Fensterarbeiten | Fensteröffnung | 0 | 7.5 |  | 1205Wa 0000003976 | 0 | - | 0,51 | AllplanAttributes - ash D_Detailverweis: <undefiniert>; U-Wert: 0.9; Schallschutzklasse: 32; Sonnenschutztyp: Movable
Fensteröffnung | H2 Ebene +2 | 1205Fen0000281223 | m² | 0 | Fensterarbeiten | Fensteröffnung | 0 | 7.5 |  | 1205Wa 0000003976 | 0 | - | 0,51 | AllplanAttributes - ash D_Detailverweis: <undefiniert>; U-Wert: 0.9; Schallschutzklasse: 32; Sonnenschutztyp: Movable
Fensteröffnung | H2 Ebene +2 | 1205Fen0000280543 | m² | 0 | Fensterarbeiten | Fensteröffnung | 0 | 7.5 |  | 1205Wa 0000003976 | 0 | - | 0,51 | AllplanAttributes - ash D_Detailverweis: <undefiniert>; U-Wert: 0.9; Schallschutzklasse: 32; Sonnenschutztyp: Movable
Fensteröffnung | H2 Ebene +2 | 1205Fen0000280777 | m² | 0 | Fensterarbeiten | Fensteröffnung | 0 | 7.5 | NEW | 1205Wa 0000003986 | 0 | - | 0,51 | AllplanAttributes - ash D_Detailverweis: <undefiniert>; U-Wert: 0.9; Schallschutzklasse: 32; Sonnenschutztyp: Movable
Fensteröffnung | H2 Ebene +2 | 1205Fen0000280927 | m² | 0 | Fensterarbeiten | Fensteröffnung | 0 | 7.5 | NEW | 1205Wa 0000003986 | 0 | - | 0,51 | AllplanAttributes - ash D_Detailverweis: <undefiniert>; U-Wert: 0.9; Schallschutzklasse: 32; Sonnenschutztyp: Movable
Fensteröffnung | H2 Ebene +2 | 1205Fen0000344915 | m² | 0 | Fensterarbeiten | Fensteröffnung | 0 | 7.5 | NEW | 1205Wa 0000003986 | 0 | - | 0,51 | AllplanAttributes - ash D_Detailverweis: <undefiniert>; U-Wert: 0.9; Schallschutzklasse: 32; Sonnenschutztyp: Movable
Fensteröffnung | H2 Ebene +2 | 1205Fen0000280947 | m² | 0 | Fensterarbeiten | Fensteröffnung | 0 | 7.5 | NEW | 1205Wa 0000003986 | 0 | - | 0,51 | AllplanAttributes - ash D_Detailverweis: <undefiniert>; U-Wert: 0.9; Schallschutzklasse: 32; Sonnenschutztyp: Movable
Fensteröffnung | H2 Ebene +2 | 1205Fen0000280769 | m² | 0 | Fensterarbeiten | Fensteröffnung | 0 | 7.5 | NEW | 1205Wa 0000003986 | 0 | - | 0,51 | AllplanAttributes - ash D_Detailverweis: <undefiniert>; U-Wert: 0.9; Schallschutzklasse: 32; Sonnenschutztyp: Movable
Fensteröffnung | H2 Ebene +2 | 1205Fen0000280685 | m² | 0 | Fensterarbeiten | Fensteröffnung | 0 | 7.5 | NEW | 1205Wa 0000003996 | 0 | - | 0,51 | AllplanAttributes - ash D_Detailverweis: <undefiniert>; U-Wert: 0.9; Schallschutzklasse: 32; Sonnenschutztyp: Movable
Fensteröffnung | H2 Ebene +2 | 1205Fen0000280453 | m² | 0 | Fensterarbeiten | Fensteröffnung | 0 | 7.5 | NEW | 1205Wa 0000003996 | 0 | - | 0,51 | AllplanAttributes - ash D_Detailverweis: <undefiniert>; U-Wert: 0.9; Schallschutzklasse: 32; Sonnenschutztyp: Movable
Fensteröffnung | H2 Ebene +2 | 1205Fen0000344914 | m² | 0 | Fensterarbeiten | Fensteröffnung | 0 | 7.5 | NEW | 1205Wa 0000003996 | 0 | - | 0,51 | AllplanAttributes - ash D_Detailverweis: <undefiniert>; U-Wert: 0.9; Schallschutzklasse: 32; Sonnenschutztyp: Movable
Fensteröffnung | H2 Ebene +2 | 1205Fen0000280655 | m² | 0 | Fensterarbeiten | Fensteröffnung | 0 | 7.5 | NEW | 1205Wa 0000003996 | 0 | - | 0,51 | AllplanAttributes - ash D_Detailverweis: <undefiniert>; U-Wert: 0.9; Schallschutzklasse: 32; Sonnenschutztyp: Movable
Fensteröffnung | H2 Ebene +2 | 1205Fen0000280641 | m² | 0 | Fensterarbeiten | Fensteröffnung | 0 | 7.5 | NEW | 1205Wa 0000003996 | 0 | - | 0,51 | AllplanAttributes - ash D_Detailverweis: <undefiniert>; U-Wert: 0.9; Schallschutzklasse: 32; Sonnenschutztyp: Movable
Fensteröffnung | H2 Ebene +2 | 1205Fen0000280887 | m² | 0 | Fensterarbeiten | Fensteröffnung | 0 | 7.5 | NEW | 1205Wa 0000004006 | 0 | - | 0,51 | AllplanAttributes - ash D_Detailverweis: <undefiniert>; U-Wert: 0.9; Schallschutzklasse: 32; Sonnenschutztyp: Movable
Fensteröffnung | H2 Ebene +2 | 1205Fen0000280499 | m² | 0 | Fensterarbeiten | Fensteröffnung | 0 | 7.5 | NEW | 1205Wa 0000004006 | 0 | - | 0,51 | AllplanAttributes - ash D_Detailverweis: <undefiniert>; U-Wert: 0.9; Schallschutzklasse: 32; Sonnenschutztyp: Movable
Fensteröffnung | H2 Ebene +2 | 1205Fen0000344913 | m² | 0 | Fensterarbeiten | Fensteröffnung | 0 | 7.5 | NEW | 1205Wa 0000004006 | 0 | - | 0,51 | AllplanAttributes - ash D_Detailverweis: <undefiniert>; U-Wert: 0.9; Schallschutzklasse: 32; Sonnenschutztyp: Movable
Fensteröffnung | H2 Ebene +2 | 1205Fen0000281011 | m² | 0 | Fensterarbeiten | Fensteröffnung | 0 | 7.5 | NEW | 1205Wa 0000004006 | 0 | - | 0,51 | AllplanAttributes - ash D_Detailverweis: <undefiniert>; U-Wert: 0.9; Schallschutzklasse: 32; Sonnenschutztyp: Movable
Fensteröffnung | H2 Ebene +2 | 1205Fen0000280409 | m² | 0 | Fensterarbeiten | Fensteröffnung | 0 | 7.5 | NEW | 1205Wa 0000004006 | 0 | - | 0,51 | AllplanAttributes - ash D_Detailverweis: <undefiniert>; U-Wert: 0.9; Schallschutzklasse: 32; Sonnenschutztyp: Movable
Fensteröffnung | H2 Ebene +2 | 1205Fen0000356074 | m² | 0 | Fensterarbeiten | Fensteröffnung | 0 | 7.5 |  | 1205Wa 0000004406 | 0 | - | 0,51 | AllplanAttributes - ash D_Detailverweis: <undefiniert>; U-Wert: 0.9; Schallschutzklasse: -; Sonnenschutztyp: Movable
Fensteröffnung | H2 Ebene +2 | 1205Fen0000356073 | m³ | 0 | Fensterarbeiten | Fensteröffnung | 0 | 7.5 |  | 1205Wa 0000004410 | 0 | - | 0,51 | AllplanAttributes - ash D_Detailverweis: <undefiniert>; U-Wert: 0.9; Schallschutzklasse: -; Sonnenschutztyp: Movable
Fensteröffnung | H2 Ebene +2 | 1205Fen0000356072 | m³ | 0 | Fensterarbeiten | Fensteröffnung | 0 | 7.5 |  | 1205Wa 0000004402 | 0 | - | 0,51 | AllplanAttributes - ash D_Detailverweis: <undefiniert>; U-Wert: 0.9; Schallschutzklasse: -; Sonnenschutztyp: Movable
Fensteröffnung | H2 Ebene +2 | 1205Fen0000356071 | m² | 0 | Fensterarbeiten | Fensteröffnung | 0 | 7.5 |  | 1205Wa 0000004398 | 0 | - | 0,51 | AllplanAttributes - ash D_Detailverweis: <undefiniert>; U-Wert: 0.9; Schallschutzklasse: -; Sonnenschutztyp: Movable
Fensteröffnung | H2 Ebene +2 | 1205Fen0000356070 | m² | 0 | Fensterarbeiten | Fensteröffnung | 0 | 7.5 | NEW | 1205Wa 0000004394 | 0 | - | 0,51 | AllplanAttributes - ash D_Detailverweis: <undefiniert>; U-Wert: 0.9; Schallschutzklasse: -; Sonnenschutztyp: Movable
Fensteröffnung | H2 Ebene +2 | 1205Fen0000356069 | m² | 0 | Fensterarbeiten | Fensteröffnung | 0 | 7.5 | NEW | 1205Wa 0000004390 | 0 | - | 0,51 | AllplanAttributes - ash D_Detailverweis: <undefiniert>; U-Wert: 0.9; Schallschutzklasse: -; Sonnenschutztyp: Movable
Fensteröffnung | H2 Ebene +2 | 1205Fen0000356068 | m² | 0 | Fensterarbeiten | Fensteröffnung | 0 | 7.5 | NEW | 1205Wa 0000004416 | 0 | - | 0,51 | AllplanAttributes - ash D_Detailverweis: <undefiniert>; U-Wert: 0.9; Schallschutzklasse: -; Sonnenschutztyp: Movable
Fensteröffnung | H2 Ebene +2 | 1205Fen2005819448 | m² | 0 | Fensterarbeiten | Fensteröffnung | 0 | 7.5 |  | 1205Wa 0000004689 | 0 | - | 0,51 | AllplanAttributes - ash D_Detailverweis: <undefiniert>; U-Wert: 0.9; Schallschutzklasse: -; Sonnenschutztyp: Movable
Fensteröffnung | H2 Ebene +2 | 1205Fen2005819447 | m³ | 0 | Fensterarbeiten | Fensteröffnung | 0 | 7.5 |  | 1205Wa 0000004693 | 0 | - | 0,51 | AllplanAttributes - ash D_Detailverweis: <undefiniert>; U-Wert: 0.9; Schallschutzklasse: -; Sonnenschutztyp: Movable
Fensteröffnung | H2 Ebene +2 | 1205Fen2005819446 | m³ | 0 | Fensterarbeiten | Fensteröffnung | 0 | 7.5 |  | 1205Wa 0000004697 | 0 | - | 0,51 | AllplanAttributes - ash D_Detailverweis: <undefiniert>; U-Wert: 0.9; Schallschutzklasse: -; Sonnenschutztyp: Movable
Fensteröffnung | H2 Ebene +2 | 1205Fen2005819445 | m² | 0 | Fensterarbeiten | Fensteröffnung | 0 | 7.5 |  | 1205Wa 0000004701 | 0 | - | 0,51 | AllplanAttributes - ash D_Detailverweis: <undefiniert>; U-Wert: 0.9; Schallschutzklasse: -; Sonnenschutztyp: Movable
Fensteröffnung | H2 Ebene +2 | 1205Fen2005819444 | m² | 0 | Fensterarbeiten | Fensteröffnung | 0 | 7.5 | NEW | 1205Wa 0000004705 | 0 | - | 0,51 | AllplanAttributes - ash D_Detailverweis: <undefiniert>; U-Wert: 0.9; Schallschutzklasse: -; Sonnenschutztyp: Movable
Fensteröffnung | H2 Ebene +2 | 1205Fen2005819443 | m² | 0 | Fensterarbeiten | Fensteröffnung | 0 | 7.5 | NEW | 1205Wa 0000004709 | 0 | - | 0,51 | AllplanAttributes - ash D_Detailverweis: <undefiniert>; U-Wert: 0.9; Schallschutzklasse: -; Sonnenschutztyp: Movable
Fensteröffnung | H2 Ebene +2 | 1205Fen2005819442 | m² | 0 | Fensterarbeiten | Fensteröffnung | 0 | 7.5 | NEW | 1205Wa 0000004713 | 0 | - | 0,51 | AllplanAttributes - ash D_Detailverweis: <undefiniert>; U-Wert: 0.9; Schallschutzklasse: 32; Sonnenschutztyp: Movable
Fensteröffnung | H2 Ebene +2 | 1205Fen2005818636 | m² | 0 | Fensterarbeiten | Fensteröffnung | 0 | 7.5 |  | 1205Wa 0000004689 | 0 | - | 0,51 | AllplanAttributes - ash D_Detailverweis: <undefiniert>; U-Wert: 0.9; Schallschutzklasse: -; Sonnenschutztyp: Movable
Fensteröffnung | H2 Ebene +2 | 1205Fen2005818635 | m³ | 0 | Fensterarbeiten | Fensteröffnung | 0 | 7.5 |  | 1205Wa 0000004693 | 0 | - | 0,51 | AllplanAttributes - ash D_Detailverweis: <undefiniert>; U-Wert: 0.9; Schallschutzklasse: -; Sonnenschutztyp: Movable
Fensteröffnung | H2 Ebene +2 | 1205Fen2005818634 | m³ | 0 | Fensterarbeiten | Fensteröffnung | 0 | 7.5 |  | 1205Wa 0000004697 | 0 | - | 0,51 | AllplanAttributes - ash D_Detailverweis: <undefiniert>; U-Wert: 0.9; Schallschutzklasse: -; Sonnenschutztyp: Movable
Fensteröffnung | H2 Ebene +2 | 1205Fen2005818633 | m² | 0 | Fensterarbeiten | Fensteröffnung | 0 | 7.5 |  | 1205Wa 0000004701 | 0 | - | 0,51 | AllplanAttributes - ash D_Detailverweis: <undefiniert>; U-Wert: 0.9; Schallschutzklasse: -; Sonnenschutztyp: Movable
Fensteröffnung | H2 Ebene +2 | 1205Fen2005818632 | m² | 0 | Fensterarbeiten | Fensteröffnung | 0 | 7.5 | NEW | 1205Wa 0000004705 | 0 | - | 0,51 | AllplanAttributes - ash D_Detailverweis: <undefiniert>; U-Wert: 0.9; Schallschutzklasse: -; Sonnenschutztyp: Movable
Fensteröffnung | H2 Ebene +2 | 1205Fen2005818631 | m² | 0 | Fensterarbeiten | Fensteröffnung | 0 | 7.5 | NEW | 1205Wa 0000004709 | 0 | - | 0,51 | AllplanAttributes - ash D_Detailverweis: <undefiniert>; U-Wert: 0.9; Schallschutzklasse: -; Sonnenschutztyp: Movable
Fensteröffnung | H2 Ebene +2 | 1205Fen2005818630 | m² | 0 | Fensterarbeiten | Fensteröffnung | 0 | 7.5 | NEW | 1205Wa 0000004713 | 0 | - | 0,51 | AllplanAttributes - ash D_Detailverweis: <undefiniert>; U-Wert: 0.9; Schallschutzklasse: 32; Sonnenschutztyp: Movable
Fensteröffnung | H2 Ebene +2 | 1205Fen2005819299 | m² | 0 | Fensterarbeiten | Fensteröffnung | 0 | 7.5 |  | 1205Wa 0000004689 | 0 | - | 0,51 | AllplanAttributes - ash D_Detailverweis: <undefiniert>; U-Wert: 0.9; Schallschutzklasse: -; Sonnenschutztyp: Movable
Fensteröffnung | H2 Ebene +2 | 1205Fen2005819298 | m³ | 0 | Fensterarbeiten | Fensteröffnung | 0 | 7.5 |  | 1205Wa 0000004693 | 0 | - | 0,51 | AllplanAttributes - ash D_Detailverweis: <undefiniert>; U-Wert: 0.9; Schallschutzklasse: -; Sonnenschutztyp: Movable
Fensteröffnung | H2 Ebene +2 | 1205Fen2005819297 | m³ | 0 | Fensterarbeiten | Fensteröffnung | 0 | 7.5 |  | 1205Wa 0000004697 | 0 | - | 0,51 | AllplanAttributes - ash D_Detailverweis: <undefiniert>; U-Wert: 0.9; Schallschutzklasse: -; Sonnenschutztyp: Movable
Fensteröffnung | H2 Ebene +2 | 1205Fen2005819296 | m² | 0 | Fensterarbeiten | Fensteröffnung | 0 | 7.5 |  | 1205Wa 0000004701 | 0 | - | 0,51 | AllplanAttributes - ash D_Detailverweis: <undefiniert>; U-Wert: 0.9; Schallschutzklasse: -; Sonnenschutztyp: Movable
Fensteröffnung | H2 Ebene +2 | 1205Fen2005819295 | m² | 0 | Fensterarbeiten | Fensteröffnung | 0 | 7.5 | NEW | 1205Wa 0000004705 | 0 | - | 0,51 | AllplanAttributes - ash D_Detailverweis: <undefiniert>; U-Wert: 0.9; Schallschutzklasse: -; Sonnenschutztyp: Movable
Fensteröffnung | H2 Ebene +2 | 1205Fen2005819294 | m² | 0 | Fensterarbeiten | Fensteröffnung | 0 | 7.5 | NEW | 1205Wa 0000004709 | 0 | - | 0,51 | AllplanAttributes - ash D_Detailverweis: <undefiniert>; U-Wert: 0.9; Schallschutzklasse: -; Sonnenschutztyp: Movable
Fensteröffnung | H2 Ebene +2 | 1205Fen2005819293 | m² | 0 | Fensterarbeiten | Fensteröffnung | 0 | 7.5 | NEW | 1205Wa 0000004713 | 0 | - | 0,51 | AllplanAttributes - ash D_Detailverweis: <undefiniert>; U-Wert: 0.9; Schallschutzklasse: 32; Sonnenschutztyp: Movable
Fensteröffnung | H2 Ebene +2 | 1205Fen2005823952 | m² | 0 | Fensterarbeiten | Fensteröffnung | 0 | 7.5 |  | 1205Wa 0000004893 | 0 | - | 0,51 | AllplanAttributes - ash D_Detailverweis: <undefiniert>; U-Wert: 0.9; Schallschutzklasse: 32; Sonnenschutztyp: Movable
Fensteröffnung | H2 Ebene +2 | 1205Fen2005823951 | m³ | 0 | Fensterarbeiten | Fensteröffnung | 0 | 7.5 |  | 1205Wa 0000004889 | 0 | - | 0,51 | AllplanAttributes - ash D_Detailverweis: <undefiniert>; U-Wert: 0.9; Schallschutzklasse: 32; Sonnenschutztyp: Movable
Fensteröffnung | H2 Ebene +2 | 1205Fen2005823950 | m³ | 0 | Fensterarbeiten | Fensteröffnung | 0 | 7.5 |  | 1205Wa 0000004885 | 0 | - | 0,51 | AllplanAttributes - ash D_Detailverweis: <undefiniert>; U-Wert: 0.9; Schallschutzklasse: 32; Sonnenschutztyp: Movable
Fensteröffnung | H2 Ebene +2 | 1205Fen2005823949 | m² | 0 | Fensterarbeiten | Fensteröffnung | 0 | 7.5 |  | 1205Wa 0000004881 | 0 | - | 0,51 | AllplanAttributes - ash D_Detailverweis: <undefiniert>; U-Wert: 0.9; Schallschutzklasse: 32; Sonnenschutztyp: Movable
Fensteröffnung | H2 Ebene +2 | 1205Fen2005823948 | m² | 0 | Fensterarbeiten | Fensteröffnung | 0 | 7.5 | NEW | 1205Wa 0000004877 | 0 | - | 0,51 | AllplanAttributes - ash D_Detailverweis: <undefiniert>; U-Wert: 0.9; Schallschutzklasse: 32; Sonnenschutztyp: Movable
Fensteröffnung | H2 Ebene +2 | 1205Fen2005823947 | m² | 0 | Fensterarbeiten | Fensteröffnung | 0 | 7.5 | NEW | 1205Wa 0000004873 | 0 | - | 0,51 | AllplanAttributes - ash D_Detailverweis: <undefiniert>; U-Wert: 0.9; Schallschutzklasse: 32; Sonnenschutztyp: Movable
Fensteröffnung | H2 Ebene +2 | 1205Fen2005823946 | m² | 0 | Fensterarbeiten | Fensteröffnung | 0 | 7.5 | NEW | 1205Wa 0000004869 | 0 | - | 0,51 | AllplanAttributes - ash D_Detailverweis: FSLH2; ash D_Plannummer: D833; U-Wert: 0.9; Schallschutzklasse: 32; Sonnenschutztyp: Movable
Fensteröffnung | H2 Ebene +2 | 1205Fen0000280157 | m² | 0 | Fensterarbeiten | Fensteröffnung | 0 | 7.5 |  | 1205Wa 0000005133 | 0 | - | 0,51 | AllplanAttributes - ash D_Detailverweis: <undefiniert>; U-Wert: 0.9; Schallschutzklasse: 32; Sonnenschutztyp: Movable
Fensteröffnung | H2 Ebene +2 | 1205Fen0000280283 | m² | 0 | Fensterarbeiten | Fensteröffnung | 0 | 7.5 |  | 1205Wa 0000005133 | 0 | - | 0,51 | AllplanAttributes - ash D_Detailverweis: <undefiniert>; U-Wert: 0.9; Schallschutzklasse: 32; Sonnenschutztyp: Movable
Fensteröffnung | H2 Ebene +2 | 1205Fen0000280190 | m² | 0 | Fensterarbeiten | Fensteröffnung | 0 | 7.5 |  | 1205Wa 0000005133 | 0 | - | 0,51 | AllplanAttributes - ash D_Detailverweis: <undefiniert>; U-Wert: 0.9; Schallschutzklasse: 32; Sonnenschutztyp: Movable
Fensteröffnung | H2 Ebene +2 | 1205Fen0000280160 | m² | 0 | Fensterarbeiten | Fensteröffnung | 0 | 7.5 |  | 1205Wa 0000005133 | 0 | - | 0,51 | AllplanAttributes - ash D_Detailverweis: <undefiniert>; U-Wert: 0.9; Schallschutzklasse: 32; Sonnenschutztyp: Movable
Fensteröffnung | H2 Ebene +2 | 1205Fen0000280112 | m² | 0 | Fensterarbeiten | Fensteröffnung | 0 | 7.5 |  | 1205Wa 0000005133 | 0 | - | 0,51 | AllplanAttributes - ash D_Detailverweis: <undefiniert>; U-Wert: 0.9; Schallschutzklasse: 32; Sonnenschutztyp: Movable
Fensteröffnung | H2 Ebene +2 | 1205Fen0000280142 | m² | 0 | Fensterarbeiten | Fensteröffnung | 0 | 7.5 |  | 1205Wa 0000005133 | 0 | - | 0,51 | AllplanAttributes - ash D_Detailverweis: <undefiniert>; U-Wert: 0.9; Schallschutzklasse: 32; Sonnenschutztyp: Movable
Fensteröffnung | H2 Ebene +2 | 1205Fen0000280437 | m³ | 0 | Fensterarbeiten | Fensteröffnung | 0 | 7.5 |  | 1205Wa 0000005124 | 0 | - | 0,51 | AllplanAttributes - ash D_Detailverweis: <undefiniert>; U-Wert: 0.9; Schallschutzklasse: 32; Sonnenschutztyp: Movable
Fensteröffnung | H2 Ebene +2 | 1205Fen0000280939 | m³ | 0 | Fensterarbeiten | Fensteröffnung | 0 | 7.5 |  | 1205Wa 0000005124 | 0 | - | 0,51 | AllplanAttributes - ash D_Detailverweis: <undefiniert>; U-Wert: 0.9; Schallschutzklasse: 32; Sonnenschutztyp: Movable
Fensteröffnung | H2 Ebene +2 | 1205Fen0000280517 | m³ | 0 | Fensterarbeiten | Fensteröffnung | 0 | 7.5 |  | 1205Wa 0000005124 | 0 | - | 0,51 | AllplanAttributes - ash D_Detailverweis: <undefiniert>; U-Wert: 0.9; Schallschutzklasse: 32; Sonnenschutztyp: Movable
Fensteröffnung | H2 Ebene +2 | 1205Fen0000280713 | m³ | 0 | Fensterarbeiten | Fensteröffnung | 0 | 7.5 |  | 1205Wa 0000005124 | 0 | - | 0,51 | AllplanAttributes - ash D_Detailverweis: <undefiniert>; U-Wert: 0.9; Schallschutzklasse: 32; Sonnenschutztyp: Movable
Fensteröffnung | H2 Ebene +2 | 1205Fen0000280891 | m³ | 0 | Fensterarbeiten | Fensteröffnung | 0 | 7.5 |  | 1205Wa 0000005124 | 0 | - | 0,51 | AllplanAttributes - ash D_Detailverweis: <undefiniert>; U-Wert: 0.9; Schallschutzklasse: 32; Sonnenschutztyp: Movable
Fensteröffnung | H2 Ebene +2 | 1205Fen0000280459 | m³ | 0 | Fensterarbeiten | Fensteröffnung | 0 | 7.5 |  | 1205Wa 0000005124 | 0 | - | 0,51 | AllplanAttributes - ash D_Detailverweis: <undefiniert>; U-Wert: 0.9; Schallschutzklasse: 32; Sonnenschutztyp: Movable
Fensteröffnung | H2 Ebene +2 | 1205Fen0000280925 | m³ | 0 | Fensterarbeiten | Fensteröffnung | 0 | 7.5 |  | 1205Wa 0000005115 | 0 | - | 0,51 | AllplanAttributes - ash D_Detailverweis: <undefiniert>; U-Wert: 0.9; Schallschutzklasse: 32; Sonnenschutztyp: Movable
Fensteröffnung | H2 Ebene +2 | 1205Fen0000280929 | m³ | 0 | Fensterarbeiten | Fensteröffnung | 0 | 7.5 |  | 1205Wa 0000005115 | 0 | - | 0,51 | AllplanAttributes - ash D_Detailverweis: <undefiniert>; U-Wert: 0.9; Schallschutzklasse: 32; Sonnenschutztyp: Movable
Fensteröffnung | H2 Ebene +2 | 1205Fen0000281203 | m³ | 0 | Fensterarbeiten | Fensteröffnung | 0 | 7.5 |  | 1205Wa 0000005115 | 0 | - | 0,51 | AllplanAttributes - ash D_Detailverweis: <undefiniert>; U-Wert: 0.9; Schallschutzklasse: 32; Sonnenschutztyp: Movable
Fensteröffnung | H2 Ebene +2 | 1205Fen0000281107 | m³ | 0 | Fensterarbeiten | Fensteröffnung | 0 | 7.5 |  | 1205Wa 0000005115 | 0 | - | 0,51 | AllplanAttributes - ash D_Detailverweis: <undefiniert>; U-Wert: 0.9; Schallschutzklasse: 32; Sonnenschutztyp: Movable
Fensteröffnung | H2 Ebene +2 | 1205Fen0000281235 | m³ | 0 | Fensterarbeiten | Fensteröffnung | 0 | 7.5 |  | 1205Wa 0000005115 | 0 | - | 0,51 | AllplanAttributes - ash D_Detailverweis: <undefiniert>; U-Wert: 0.9; Schallschutzklasse: 32; Sonnenschutztyp: Movable
Fensteröffnung | H2 Ebene +2 | 1205Fen0000280985 | m³ | 0 | Fensterarbeiten | Fensteröffnung | 0 | 7.5 |  | 1205Wa 0000005115 | 0 | - | 0,51 | AllplanAttributes - ash D_Detailverweis: <undefiniert>; U-Wert: 0.9; Schallschutzklasse: 32; Sonnenschutztyp: Movable
Fensteröffnung | H2 Ebene +2 | 1205Fen0000280869 | m² | 0 | Fensterarbeiten | Fensteröffnung | 0 | 7.5 |  | 1205Wa 0000005106 | 0 | - | 0,51 | AllplanAttributes - ash D_Detailverweis: <undefiniert>; U-Wert: 0.9; Schallschutzklasse: 32; Sonnenschutztyp: Movable
Fensteröffnung | H2 Ebene +2 | 1205Fen0000280417 | m² | 0 | Fensterarbeiten | Fensteröffnung | 0 | 7.5 |  | 1205Wa 0000005106 | 0 | - | 0,51 | AllplanAttributes - ash D_Detailverweis: <undefiniert>; U-Wert: 0.9; Schallschutzklasse: 32; Sonnenschutztyp: Movable
Fensteröffnung | H2 Ebene +2 | 1205Fen0000280825 | m² | 0 | Fensterarbeiten | Fensteröffnung | 0 | 7.5 |  | 1205Wa 0000005106 | 0 | - | 0,51 | AllplanAttributes - ash D_Detailverweis: <undefiniert>; U-Wert: 0.9; Schallschutzklasse: 32; Sonnenschutztyp: Movable
Fensteröffnung | H2 Ebene +2 | 1205Fen0000280413 | m² | 0 | Fensterarbeiten | Fensteröffnung | 0 | 7.5 |  | 1205Wa 0000005106 | 0 | - | 0,51 | AllplanAttributes - ash D_Detailverweis: <undefiniert>; U-Wert: 0.9; Schallschutzklasse: 32; Sonnenschutztyp: Movable
Fensteröffnung | H2 Ebene +2 | 1205Fen0000280981 | m² | 0 | Fensterarbeiten | Fensteröffnung | 0 | 7.5 |  | 1205Wa 0000005106 | 0 | - | 0,51 | AllplanAttributes - ash D_Detailverweis: <undefiniert>; U-Wert: 0.9; Schallschutzklasse: 32; Sonnenschutztyp: Movable
Fensteröffnung | H2 Ebene +2 | 1205Fen0000280767 | m² | 0 | Fensterarbeiten | Fensteröffnung | 0 | 7.5 |  | 1205Wa 0000005106 | 0 | - | 0,51 | AllplanAttributes - ash D_Detailverweis: <undefiniert>; U-Wert: 0.9; Schallschutzklasse: 32; Sonnenschutztyp: Movable
Fensteröffnung | H2 Ebene +2 | 1205Fen0000280719 | m² | 0 | Fensterarbeiten | Fensteröffnung | 0 | 7.5 | NEW | 1205Wa 0000005097 | 0 | - | 0,51 | AllplanAttributes - ash D_Detailverweis: <undefiniert>; U-Wert: 0.9; Schallschutzklasse: 32; Sonnenschutztyp: Movable
Fensteröffnung | H2 Ebene +2 | 1205Fen0000280755 | m² | 0 | Fensterarbeiten | Fensteröffnung | 0 | 7.5 | NEW | 1205Wa 0000005097 | 0 | - | 0,51 | AllplanAttributes - ash D_Detailverweis: <undefiniert>; U-Wert: 0.9; Schallschutzklasse: 32; Sonnenschutztyp: Movable
Fensteröffnung | H2 Ebene +2 | 1205Fen0000280959 | m² | 0 | Fensterarbeiten | Fensteröffnung | 0 | 7.5 | NEW | 1205Wa 0000005097 | 0 | - | 0,51 | AllplanAttributes - ash D_Detailverweis: <undefiniert>; U-Wert: 0.9; Schallschutzklasse: 32; Sonnenschutztyp: Movable
Fensteröffnung | H2 Ebene +2 | 1205Fen0000280787 | m² | 0 | Fensterarbeiten | Fensteröffnung | 0 | 7.5 | NEW | 1205Wa 0000005097 | 0 | - | 0,51 | AllplanAttributes - ash D_Detailverweis: <undefiniert>; U-Wert: 0.9; Schallschutzklasse: 32; Sonnenschutztyp: Movable
Fensteröffnung | H2 Ebene +2 | 1205Fen0000280837 | m² | 0 | Fensterarbeiten | Fensteröffnung | 0 | 7.5 | NEW | 1205Wa 0000005097 | 0 | - | 0,51 | AllplanAttributes - ash D_Detailverweis: <undefiniert>; U-Wert: 0.9; Schallschutzklasse: 32; Sonnenschutztyp: Movable
Fensteröffnung | H2 Ebene +2 | 1205Fen0000280623 | m² | 0 | Fensterarbeiten | Fensteröffnung | 0 | 7.5 | NEW | 1205Wa 0000005097 | 0 | - | 0,51 | AllplanAttributes - ash D_Detailverweis: <undefiniert>; U-Wert: 0.9; Schallschutzklasse: 32; Sonnenschutztyp: Movable
Fensteröffnung | H2 Ebene +2 | 1205Fen0000281019 | m² | 0 | Fensterarbeiten | Fensteröffnung | 0 | 7.5 | NEW | 1205Wa 0000005088 | 0 | - | 0,51 | AllplanAttributes - ash D_Detailverweis: <undefiniert>; U-Wert: 0.9; Schallschutzklasse: 32; Sonnenschutztyp: Movable
Fensteröffnung | H2 Ebene +2 | 1205Fen0000280485 | m² | 0 | Fensterarbeiten | Fensteröffnung | 0 | 7.5 | NEW | 1205Wa 0000005088 | 0 | - | 0,51 | AllplanAttributes - ash D_Detailverweis: <undefiniert>; U-Wert: 0.9; Schallschutzklasse: 32; Sonnenschutztyp: Movable
Fensteröffnung | H2 Ebene +2 | 1205Fen0000280859 | m² | 0 | Fensterarbeiten | Fensteröffnung | 0 | 7.5 | NEW | 1205Wa 0000005088 | 0 | - | 0,51 | AllplanAttributes - ash D_Detailverweis: <undefiniert>; U-Wert: 0.9; Schallschutzklasse: 32; Sonnenschutztyp: Movable
Fensteröffnung | H2 Ebene +2 | 1205Fen0000280753 | m² | 0 | Fensterarbeiten | Fensteröffnung | 0 | 7.5 | NEW | 1205Wa 0000005088 | 0 | - | 0,51 | AllplanAttributes - ash D_Detailverweis: <undefiniert>; U-Wert: 0.9; Schallschutzklasse: 32; Sonnenschutztyp: Movable
Fensteröffnung | H2 Ebene +2 | 1205Fen0000280483 | m² | 0 | Fensterarbeiten | Fensteröffnung | 0 | 7.5 | NEW | 1205Wa 0000005088 | 0 | - | 0,51 | AllplanAttributes - ash D_Detailverweis: <undefiniert>; U-Wert: 0.9; Schallschutzklasse: 32; Sonnenschutztyp: Movable
Fensteröffnung | H2 Ebene +2 | 1205Fen0000281087 | m² | 0 | Fensterarbeiten | Fensteröffnung | 0 | 7.5 | NEW | 1205Wa 0000005088 | 0 | - | 0,51 | AllplanAttributes - ash D_Detailverweis: <undefiniert>; U-Wert: 0.9; Schallschutzklasse: 32; Sonnenschutztyp: Movable
Fensteröffnung | H2 Ebene +2 | 1205Fen0000280497 | m² | 0 | Fensterarbeiten | Fensteröffnung | 0 | 7.5 | NEW | 1205Wa 0000005079 | 0 | - | 0,51 | AllplanAttributes - ash D_Detailverweis: <undefiniert>; U-Wert: 0.9; Schallschutzklasse: 32; Sonnenschutztyp: Movable
Fensteröffnung | H2 Ebene +2 | 1205Fen0000280449 | m² | 0 | Fensterarbeiten | Fensteröffnung | 0 | 7.5 | NEW | 1205Wa 0000005079 | 0 | - | 0,51 | AllplanAttributes - ash D_Detailverweis: <undefiniert>; U-Wert: 0.9; Schallschutzklasse: 32; Sonnenschutztyp: Movable
Fensteröffnung | H2 Ebene +2 | 1205Fen0000280961 | m² | 0 | Fensterarbeiten | Fensteröffnung | 0 | 7.5 | NEW | 1205Wa 0000005079 | 0 | - | 0,51 | AllplanAttributes - ash D_Detailverweis: <undefiniert>; U-Wert: 0.9; Schallschutzklasse: 32; Sonnenschutztyp: Movable
Fensteröffnung | H2 Ebene +2 | 1205Fen0000281065 | m² | 0 | Fensterarbeiten | Fensteröffnung | 0 | 7.5 | NEW | 1205Wa 0000005079 | 0 | - | 0,51 | AllplanAttributes - ash D_Detailverweis: <undefiniert>; U-Wert: 0.9; Schallschutzklasse: 32; Sonnenschutztyp: Movable
Fensteröffnung | H2 Ebene +2 | 1205Fen0000280649 | m² | 0 | Fensterarbeiten | Fensteröffnung | 0 | 7.5 | NEW | 1205Wa 0000005079 | 0 | - | 0,51 | AllplanAttributes - ash D_Detailverweis: <undefiniert>; U-Wert: 0.9; Schallschutzklasse: 32; Sonnenschutztyp: Movable
Fensteröffnung | H2 Ebene +2 | 1205Fen0000280461 | m² | 0 | Fensterarbeiten | Fensteröffnung | 0 | 7.5 | NEW | 1205Wa 0000005079 | 0 | - | 0,51 | AllplanAttributes - ash D_Detailverweis: <undefiniert>; U-Wert: 0.9; Schallschutzklasse: 32; Sonnenschutztyp: Movable
Fensteröffnung | H2 Ebene +2 | 1205Fen0000280029 | m² |  | Fensterarbeiten | Fensteröffnung |  | 7.5 |  | 1205Wa 0000002335 | 0 | - | 0,51 | AllplanAttributes - ash D_Detailverweis: <undefiniert>; U-Wert: 0.9; Schallschutzklasse: 32; Sonnenschutztyp: Movable
Fensteröffnung | H2 Ebene +2 | 1205Fen0000280061 | m³ | 0 | Fensterarbeiten | Fensteröffnung | 0 | 7.5 |  | 1205Wa 0000002341 | 0 | - | 0,51 | AllplanAttributes - ash D_Detailverweis: <undefiniert>; U-Wert: 0.9; Schallschutzklasse: 32; Sonnenschutztyp: Movable
Fensteröffnung | H2 Ebene +2 | 1205Fen0000280073 | m² | 0 | Fensterarbeiten | Fensteröffnung | 0 | 7.5 |  | 1205Wa 0000002347 | 0 | - | 0,51 | AllplanAttributes - ash D_Detailverweis: <undefiniert>; U-Wert: 0.9; Schallschutzklasse: 32; Sonnenschutztyp: Movable
Fensteröffnung | H2 Ebene +2 | 1205Fen0000280069 | m² | 0 | Fensterarbeiten | Fensteröffnung | 0 | 7.5 |  | 1205Wa 0000002353 | 0 | - | 0,51 | AllplanAttributes - ash D_Detailverweis: <undefiniert>; U-Wert: 0.9; Schallschutzklasse: 32; Sonnenschutztyp: Movable
Fensteröffnung | H2 Ebene +2 | 1205Fen0000280047 | m² | 0 | Fensterarbeiten | Fensteröffnung | 0 | 7.5 | NEW | 1205Wa 0000002359 | 0 | - | 0,51 | AllplanAttributes - ash D_Detailverweis: <undefiniert>; U-Wert: 0.9; Schallschutzklasse: 32; Sonnenschutztyp: Movable
Fensteröffnung | H2 Ebene +2 | 1205Fen0000280057 | m² | 0 | Fensterarbeiten | Fensteröffnung | 0 | 7.5 | NEW | 1205Wa 0000092760 | 0 | - | 0,51 | AllplanAttributes - ash D_Detailverweis: FS TR; ash D_Plannummer: D1530; U-Wert: 0.9; Schallschutzklasse: 32; Sonnenschutztyp: Movable
Fensteröffnung | H2 Ebene +2 | 1205Fen0000280038 | m² |  | Fensterarbeiten | Fensteröffnung |  | 7.5 |  | 1205Wa 0000003016 | 0 | - | 0,51 | AllplanAttributes - ash D_Detailverweis: <undefiniert>; U-Wert: 0.9; Schallschutzklasse: -; Sonnenschutztyp: Movable
Fensteröffnung | H2 Ebene +2 | 1205Fen0000280065 | m³ | 0 | Fensterarbeiten | Fensteröffnung | 0 | 7.5 |  | 1205Wa 0000002967 | 0 | - | 0,51 | AllplanAttributes - ash D_Detailverweis: <undefiniert>; U-Wert: 0.9; Schallschutzklasse: -; Sonnenschutztyp: Movable
Fensteröffnung | H2 Ebene +2 | 1205Fen0000280083 | m² | 0 | Fensterarbeiten | Fensteröffnung | 0 | 7.5 |  | 1205Wa 0000002971 | 0 | - | 0,51 | AllplanAttributes - ash D_Detailverweis: <undefiniert>; U-Wert: 0.9; Schallschutzklasse: -; Sonnenschutztyp: Movable
Fensteröffnung | H2 Ebene +2 | 1205Fen0000280055 | m² | 0 | Fensterarbeiten | Fensteröffnung | 0 | 7.5 |  | 1205Wa 0000002975 | 0 | - | 0,51 | AllplanAttributes - ash D_Detailverweis: <undefiniert>; U-Wert: 0.9; Schallschutzklasse: -; Sonnenschutztyp: Movable
Fensteröffnung | H2 Ebene +2 | 1205Fen0000280043 | m² | 0 | Fensterarbeiten | Fensteröffnung | 0 | 7.5 | NEW | 1205Wa 0000002979 | 0 | - | 0,51 | AllplanAttributes - ash D_Detailverweis: <undefiniert>; U-Wert: 0.9; Schallschutzklasse: -; Sonnenschutztyp: Movable
Fensteröffnung | H2 Ebene +2 | 1205Fen0000280081 | m² | 0 | Fensterarbeiten | Fensteröffnung | 0 | 7.5 | NEW | 1205Wa 0000091817 | 0 | - | 0,51 | AllplanAttributes - ash D_Detailverweis: <undefiniert>; U-Wert: 0.9; Schallschutzklasse: -; Sonnenschutztyp: Movable
Fensteröffnung | H2 Ebene +2 | 1205Fen0000280271 | m² |  | Wärmedämm-Verbundsysteme | Fensteröffnung |  | 7.5 | NEW | 1205Wa 0000101990 | 0 | - | 0,51 | AllplanAttributes - Material: Fensterelement; Tragendes Bauteil: no; Brandabschnittsdefinierendes Bauteil: no; ash D_Detailverweis: <undefiniert>; U-Wert: 0.9; Schallschutzklasse: 32; Sonnenschutztyp: Movable
Fensteröffnung | H2 Ebene +2 | 1205Fen0000280723 | m³ | 0 | Wärmedämm-Verbundsysteme | Fensteröffnung | 0 | 7.5 | NEW | 1205Wa 0000102005 | 0 | - | 0,51 | AllplanAttributes - Material: Fensterelement; Außenliegend: yes; ash D_Detailverweis: <undefiniert>; U-Wert: 0.9; Schallschutzklasse: 32; Sonnenschutztyp: Movable
Fensteröffnung | H2 Ebene +2 | 1205Fen0000280897 | m³ | 0 | Wärmedämm-Verbundsysteme | Fensteröffnung | 0 | 7.5 | NEW | 1205Wa 0000102020 | 0 | - | 0,51 | AllplanAttributes - ash D_Detailverweis: <undefiniert>; U-Wert: 0.9; Schallschutzklasse: 32; Sonnenschutztyp: Movable
Fensteröffnung | H2 Ebene +2 | 1205Fen0000280597 | m² | 0 | Wärmedämm-Verbundsysteme | Fensteröffnung | 0 | 7.5 | NEW | 1205Wa 0000102017 | 0 | - | 0,51 | AllplanAttributes - ash D_Detailverweis: <undefiniert>; U-Wert: 0.9; Schallschutzklasse: 32; Sonnenschutztyp: Movable
Fensteröffnung | H2 Ebene +2 | 1205Fen0000281179 | m² | 0 | Wärmedämm-Verbundsysteme | Fensteröffnung | 0 | 7.5 | NEW | 1205Wa 0000102014 | 0 | - | 0,51 | AllplanAttributes - ash D_Detailverweis: <undefiniert>; U-Wert: 0.9; Schallschutzklasse: 32; Sonnenschutztyp: Movable
Fensteröffnung | H2 Ebene +2 | 1205Fen0000280661 | m² | 0 | Wärmedämm-Verbundsysteme | Fensteröffnung | 0 | 7.5 | NEW | 1205Wa 0000102011 | 0 | - | 0,51 | AllplanAttributes - ash D_Detailverweis: <undefiniert>; U-Wert: 0.9; Schallschutzklasse: 32; Sonnenschutztyp: Movable
Fensteröffnung | H2 Ebene +2 | 1205Fen0000281095 | m² | 0 | Wärmedämm-Verbundsysteme | Fensteröffnung | 0 | 7.5 | NEW | 1205Wa 0000102008 | 0 | - | 0,51 | AllplanAttributes - ash D_Detailverweis: <undefiniert>; U-Wert: 0.9; Schallschutzklasse: 32; Sonnenschutztyp: Movable
Fensteröffnung | H2 Ebene +2 | 1205Fen0000280148 | m² |  | Fensterarbeiten | Fensteröffnung |  | 7.5 |  | 1205Wa 0000102069 | 0 | - | 0,51 | AllplanAttributes - ash D_Detailverweis: <undefiniert>; U-Wert: 0.9; Schallschutzklasse: 32; Sonnenschutztyp: Movable
Fensteröffnung | H2 Ebene +2 | 1205Fen0000281207 | m³ | 0 | Fensterarbeiten | Fensteröffnung | 0 | 7.5 |  | 1205Wa 0000102066 | 0 | - | 0,51 | AllplanAttributes - ash D_Detailverweis: <undefiniert>; U-Wert: 0.9; Schallschutzklasse: 32; Sonnenschutztyp: Movable
Fensteröffnung | H2 Ebene +2 | 1205Fen0000281115 | m³ | 0 | Fensterarbeiten | Fensteröffnung | 0 | 7.5 |  | 1205Wa 0000102063 | 0 | - | 0,51 | AllplanAttributes - ash D_Detailverweis: <undefiniert>; U-Wert: 0.9; Schallschutzklasse: 32; Sonnenschutztyp: Movable
Fensteröffnung | H2 Ebene +2 | 1205Fen0000281051 | m² | 0 | Fensterarbeiten | Fensteröffnung | 0 | 7.5 |  | 1205Wa 0000102060 | 0 | - | 0,51 | AllplanAttributes - ash D_Detailverweis: <undefiniert>; U-Wert: 0.9; Schallschutzklasse: 32; Sonnenschutztyp: Movable
Fensteröffnung | H2 Ebene +2 | 1205Fen0000281213 | m² | 0 | Fensterarbeiten | Fensteröffnung | 0 | 7.5 | NEW | 1205Wa 0000102057 | 0 | - | 0,51 | AllplanAttributes - ash D_Detailverweis: <undefiniert>; U-Wert: 0.9; Schallschutzklasse: 32; Sonnenschutztyp: Movable
Fensteröffnung | H2 Ebene +2 | 1205Fen0000281057 | m² | 0 | Fensterarbeiten | Fensteröffnung | 0 | 7.5 | NEW | 1205Wa 0000102054 | 0 | - | 0,51 | AllplanAttributes - ash D_Detailverweis: <undefiniert>; U-Wert: 0.9; Schallschutzklasse: 32; Sonnenschutztyp: Movable
Fensteröffnung | H2 Ebene +2 | 1205Fen0000280813 | m² | 0 | Fensterarbeiten | Fensteröffnung | 0 | 7.5 | NEW | 1205Wa 0000102051 | 0 | - | 0,51 | AllplanAttributes - ash D_Detailverweis: <undefiniert>; U-Wert: 0.9; Schallschutzklasse: 32; Sonnenschutztyp: Movable
Fensteröffnung | H2 Ebene +2 | 1205Fen2005824551 | m² | 0 | Fensterarbeiten | Fensteröffnung | 0 | 7.5 |  | 1205Wa 0000004689 | 0 | - | 0,51 | AllplanAttributes - ash D_Detailverweis: <undefiniert>; U-Wert: 0.9; Schallschutzklasse: -; Sonnenschutztyp: Movable
Fensteröffnung | H2 Ebene +2 | 1205Fen2005824453 | m² | 0 | Fensterarbeiten | Fensteröffnung | 0 | 7.5 |  | 1205Wa 0000004689 | 0 | - | 0,51 | AllplanAttributes - ash D_Detailverweis: <undefiniert>; U-Wert: 0.9; Schallschutzklasse: -; Sonnenschutztyp: Movable
Fensteröffnung | H2 Ebene +2 | 1205Fen2005824550 | m³ | 0 | Fensterarbeiten | Fensteröffnung | 0 | 7.5 |  | 1205Wa 0000004693 | 0 | - | 0,51 | AllplanAttributes - ash D_Detailverweis: <undefiniert>; U-Wert: 0.9; Schallschutzklasse: -; Sonnenschutztyp: Movable
Fensteröffnung | H2 Ebene +2 | 1205Fen2005824452 | m³ | 0 | Fensterarbeiten | Fensteröffnung | 0 | 7.5 |  | 1205Wa 0000004693 | 0 | - | 0,51 | AllplanAttributes - ash D_Detailverweis: <undefiniert>; U-Wert: 0.9; Schallschutzklasse: -; Sonnenschutztyp: Movable
Fensteröffnung | H2 Ebene +2 | 1205Fen2005824549 | m³ | 0 | Fensterarbeiten | Fensteröffnung | 0 | 7.5 |  | 1205Wa 0000004697 | 0 | - | 0,51 | AllplanAttributes - ash D_Detailverweis: <undefiniert>; U-Wert: 0.9; Schallschutzklasse: -; Sonnenschutztyp: Movable
Fensteröffnung | H2 Ebene +2 | 1205Fen2005824451 | m³ | 0 | Fensterarbeiten | Fensteröffnung | 0 | 7.5 |  | 1205Wa 0000004697 | 0 | - | 0,51 | AllplanAttributes - ash D_Detailverweis: <undefiniert>; U-Wert: 0.9; Schallschutzklasse: -; Sonnenschutztyp: Movable
Fensteröffnung | H2 Ebene +2 | 1205Fen2005824548 | m² | 0 | Fensterarbeiten | Fensteröffnung | 0 | 7.5 |  | 1205Wa 0000004701 | 0 | - | 0,51 | AllplanAttributes - ash D_Detailverweis: <undefiniert>; U-Wert: 0.9; Schallschutzklasse: -; Sonnenschutztyp: Movable
Fensteröffnung | H2 Ebene +2 | 1205Fen2005824450 | m² | 0 | Fensterarbeiten | Fensteröffnung | 0 | 7.5 |  | 1205Wa 0000004701 | 0 | - | 0,51 | AllplanAttributes - ash D_Detailverweis: <undefiniert>; U-Wert: 0.9; Schallschutzklasse: -; Sonnenschutztyp: Movable
Fensteröffnung | H2 Ebene +2 | 1205Fen2005824547 | m² | 0 | Fensterarbeiten | Fensteröffnung | 0 | 7.5 | NEW | 1205Wa 0000004705 | 0 | - | 0,51 | AllplanAttributes - ash D_Detailverweis: <undefiniert>; U-Wert: 0.9; Schallschutzklasse: -; Sonnenschutztyp: Movable
Fensteröffnung | H2 Ebene +2 | 1205Fen2005824449 | m² | 0 | Fensterarbeiten | Fensteröffnung | 0 | 7.5 | NEW | 1205Wa 0000004705 | 0 | - | 0,51 | AllplanAttributes - ash D_Detailverweis: <undefiniert>; U-Wert: 0.9; Schallschutzklasse: -; Sonnenschutztyp: Movable
Fensteröffnung | H2 Ebene +2 | 1205Fen2005824546 | m² | 0 | Fensterarbeiten | Fensteröffnung | 0 | 7.5 | NEW | 1205Wa 0000004709 | 0 | - | 0,51 | AllplanAttributes - ash D_Detailverweis: <undefiniert>; U-Wert: 0.9; Schallschutzklasse: -; Sonnenschutztyp: Movable
Fensteröffnung | H2 Ebene +2 | 1205Fen2005824448 | m² | 0 | Fensterarbeiten | Fensteröffnung | 0 | 7.5 | NEW | 1205Wa 0000004709 | 0 | - | 0,51 | AllplanAttributes - ash D_Detailverweis: <undefiniert>; U-Wert: 0.9; Schallschutzklasse: -; Sonnenschutztyp: Movable
Fensteröffnung | H2 Ebene +2 | 1205Fen2005824545 | m² | 0 | Fensterarbeiten | Fensteröffnung | 0 | 7.5 | NEW | 1205Wa 0000004713 | 0 | - | 0,51 | AllplanAttributes - ash D_Detailverweis: <undefiniert>; U-Wert: 0.9; Schallschutzklasse: 32; Sonnenschutztyp: Movable
Fensteröffnung | H2 Ebene +2 | 1205Fen2005824447 | m² | 0 | Fensterarbeiten | Fensteröffnung | 0 | 7.5 | NEW | 1205Wa 0000004713 | 0 | - | 0,51 | AllplanAttributes - ash D_Detailverweis: <undefiniert>; U-Wert: 0.9; Schallschutzklasse: 32; Sonnenschutztyp: Movable
Fensteröffnung | H2 Ebene +2 | 1205Fen2005819675 | m² | 0 | Fensterarbeiten | Fensteröffnung | 0 | 7.5 |  | 1205Wa 0000004689 | 0 | - | 0,51 | AllplanAttributes - ash D_Detailverweis: <undefiniert>; U-Wert: 0.9; Schallschutzklasse: -; Sonnenschutztyp: Movable
Fensteröffnung | H2 Ebene +2 | 1205Fen2005819532 | m² | 0 | Fensterarbeiten | Fensteröffnung | 0 | 7.5 |  | 1205Wa 0000004689 | 0 | - | 0,51 | AllplanAttributes - ash D_Detailverweis: <undefiniert>; U-Wert: 0.9; Schallschutzklasse: -; Sonnenschutztyp: Movable
Fensteröffnung | H2 Ebene +2 | 1205Fen2005819674 | m³ | 0 | Fensterarbeiten | Fensteröffnung | 0 | 7.5 |  | 1205Wa 0000004693 | 0 | - | 0,51 | AllplanAttributes - ash D_Detailverweis: <undefiniert>; U-Wert: 0.9; Schallschutzklasse: -; Sonnenschutztyp: Movable
Fensteröffnung | H2 Ebene +2 | 1205Fen2005819531 | m³ | 0 | Fensterarbeiten | Fensteröffnung | 0 | 7.5 |  | 1205Wa 0000004693 | 0 | - | 0,51 | AllplanAttributes - ash D_Detailverweis: <undefiniert>; U-Wert: 0.9; Schallschutzklasse: -; Sonnenschutztyp: Movable
Fensteröffnung | H2 Ebene +2 | 1205Fen2005819673 | m³ | 0 | Fensterarbeiten | Fensteröffnung | 0 | 7.5 |  | 1205Wa 0000004697 | 0 | - | 0,51 | AllplanAttributes - ash D_Detailverweis: <undefiniert>; U-Wert: 0.9; Schallschutzklasse: -; Sonnenschutztyp: Movable
Fensteröffnung | H2 Ebene +2 | 1205Fen2005819530 | m³ | 0 | Fensterarbeiten | Fensteröffnung | 0 | 7.5 |  | 1205Wa 0000004697 | 0 | - | 0,51 | AllplanAttributes - ash D_Detailverweis: <undefiniert>; U-Wert: 0.9; Schallschutzklasse: -; Sonnenschutztyp: Movable
Fensteröffnung | H2 Ebene +2 | 1205Fen2005819672 | m² | 0 | Fensterarbeiten | Fensteröffnung | 0 | 7.5 |  | 1205Wa 0000004701 | 0 | - | 0,51 | AllplanAttributes - ash D_Detailverweis: <undefiniert>; U-Wert: 0.9; Schallschutzklasse: -; Sonnenschutztyp: Movable
Fensteröffnung | H2 Ebene +2 | 1205Fen2005819529 | m² | 0 | Fensterarbeiten | Fensteröffnung | 0 | 7.5 |  | 1205Wa 0000004701 | 0 | - | 0,51 | AllplanAttributes - ash D_Detailverweis: <undefiniert>; U-Wert: 0.9; Schallschutzklasse: -; Sonnenschutztyp: Movable
Fensteröffnung | H2 Ebene +2 | 1205Fen2005819671 | m² | 0 | Fensterarbeiten | Fensteröffnung | 0 | 7.5 | NEW | 1205Wa 0000004705 | 0 | - | 0,51 | AllplanAttributes - ash D_Detailverweis: <undefiniert>; U-Wert: 0.9; Schallschutzklasse: -; Sonnenschutztyp: Movable
Fensteröffnung | H2 Ebene +2 | 1205Fen2005819528 | m² | 0 | Fensterarbeiten | Fensteröffnung | 0 | 7.5 | NEW | 1205Wa 0000004705 | 0 | - | 0,51 | AllplanAttributes - ash D_Detailverweis: <undefiniert>; U-Wert: 0.9; Schallschutzklasse: -; Sonnenschutztyp: Movable
Fensteröffnung | H2 Ebene +2 | 1205Fen2005819670 | m² | 0 | Fensterarbeiten | Fensteröffnung | 0 | 7.5 | NEW | 1205Wa 0000004709 | 0 | - | 0,51 | AllplanAttributes - ash D_Detailverweis: <undefiniert>; U-Wert: 0.9; Schallschutzklasse: -; Sonnenschutztyp: Movable
Fensteröffnung | H2 Ebene +2 | 1205Fen2005819527 | m² | 0 | Fensterarbeiten | Fensteröffnung | 0 | 7.5 | NEW | 1205Wa 0000004709 | 0 | - | 0,51 | AllplanAttributes - ash D_Detailverweis: <undefiniert>; U-Wert: 0.9; Schallschutzklasse: -; Sonnenschutztyp: Movable
Fensteröffnung | H2 Ebene +2 | 1205Fen2005819669 | m² | 0 | Fensterarbeiten | Fensteröffnung | 0 | 7.5 | NEW | 1205Wa 0000004713 | 0 | - | 0,51 | AllplanAttributes - ash D_Detailverweis: <undefiniert>; U-Wert: 0.9; Schallschutzklasse: 32; Sonnenschutztyp: Movable
Fensteröffnung | H2 Ebene +2 | 1205Fen2005819526 | m² | 0 | Fensterarbeiten | Fensteröffnung | 0 | 7.5 | NEW | 1205Wa 0000004713 | 0 | - | 0,51 | AllplanAttributes - ash D_Detailverweis: <undefiniert>; U-Wert: 0.9; Schallschutzklasse: 32; Sonnenschutztyp: Movable
Fensteröffnung | H2 Ebene +2 | 1205Fen0000280172 | m² |  | Fensterarbeiten | Fensteröffnung |  | 7.5 |  | 1205Wa 0000180852 | 0 | - | 0,51 | AllplanAttributes - ash D_Detailverweis: <undefiniert>; U-Wert: 0.9; Schallschutzklasse: 32; Sonnenschutztyp: Movable
Fensteröffnung | H2 Ebene +2 | 1205Fen0000280187 | m² |  | Fensterarbeiten | Fensteröffnung |  | 7.5 |  | 1205Wa 0000180852 | 0 | - | 0,51 | AllplanAttributes - ash D_Detailverweis: <undefiniert>; U-Wert: 0.9; Schallschutzklasse: 32; Sonnenschutztyp: Movable
Fensteröffnung | H2 Ebene +2 | 1205Fen0000281137 | m³ | 0 | Fensterarbeiten | Fensteröffnung | 0 | 7.5 |  | 1205Wa 0000180851 | 0 | - | 0,51 | AllplanAttributes - ash D_Detailverweis: <undefiniert>; U-Wert: 0.9; Schallschutzklasse: 32; Sonnenschutztyp: Movable
Fensteröffnung | H2 Ebene +2 | 1205Fen0000281227 | m³ | 0 | Fensterarbeiten | Fensteröffnung | 0 | 7.5 |  | 1205Wa 0000180851 | 0 | - | 0,51 | AllplanAttributes - ash D_Detailverweis: <undefiniert>; U-Wert: 0.9; Schallschutzklasse: 32; Sonnenschutztyp: Movable
Fensteröffnung | H2 Ebene +2 | 1205Fen0000281143 | m³ | 0 | Fensterarbeiten | Fensteröffnung | 0 | 7.5 |  | 1205Wa 0000180850 | 0 | - | 0,51 | AllplanAttributes - ash D_Detailverweis: <undefiniert>; U-Wert: 0.9; Schallschutzklasse: 32; Sonnenschutztyp: Movable
Fensteröffnung | H2 Ebene +2 | 1205Fen0000281159 | m³ | 0 | Fensterarbeiten | Fensteröffnung | 0 | 7.5 |  | 1205Wa 0000180850 | 0 | - | 0,51 | AllplanAttributes - ash D_Detailverweis: <undefiniert>; U-Wert: 0.9; Schallschutzklasse: 32; Sonnenschutztyp: Movable
Fensteröffnung | H2 Ebene +2 | 1205Fen0000280847 | m² | 0 | Fensterarbeiten | Fensteröffnung | 0 | 7.5 |  | 1205Wa 0000180849 | 0 | - | 0,51 | AllplanAttributes - ash D_Detailverweis: <undefiniert>; U-Wert: 0.9; Schallschutzklasse: 32; Sonnenschutztyp: Movable
Fensteröffnung | H2 Ebene +2 | 1205Fen0000280551 | m² | 0 | Fensterarbeiten | Fensteröffnung | 0 | 7.5 |  | 1205Wa 0000180849 | 0 | - | 0,51 | AllplanAttributes - ash D_Detailverweis: <undefiniert>; U-Wert: 0.9; Schallschutzklasse: 32; Sonnenschutztyp: Movable
Fensteröffnung | H2 Ebene +2 | 1205Fen0000280853 | m² | 0 | Fensterarbeiten | Fensteröffnung | 0 | 7.5 | NEW | 1205Wa 0000180848 | 0 | - | 0,51 | AllplanAttributes - ash D_Detailverweis: <undefiniert>; U-Wert: 0.9; Schallschutzklasse: 32; Sonnenschutztyp: Movable
Fensteröffnung | H2 Ebene +2 | 1205Fen0000280667 | m² | 0 | Fensterarbeiten | Fensteröffnung | 0 | 7.5 | NEW | 1205Wa 0000180848 | 0 | - | 0,51 | AllplanAttributes - ash D_Detailverweis: <undefiniert>; U-Wert: 0.9; Schallschutzklasse: 32; Sonnenschutztyp: Movable
Fensteröffnung | H2 Ebene +2 | 1205Fen0000280583 | m² | 0 | Fensterarbeiten | Fensteröffnung | 0 | 7.5 | NEW | 1205Wa 0000180847 | 0 | - | 0,51 | AllplanAttributes - ash D_Detailverweis: <undefiniert>; U-Wert: 0.9; Schallschutzklasse: 32; Sonnenschutztyp: Movable
Fensteröffnung | H2 Ebene +2 | 1205Fen0000280563 | m² | 0 | Fensterarbeiten | Fensteröffnung | 0 | 7.5 | NEW | 1205Wa 0000180847 | 0 | - | 0,51 | AllplanAttributes - ash D_Detailverweis: <undefiniert>; U-Wert: 0.9; Schallschutzklasse: 32; Sonnenschutztyp: Movable
Fensteröffnung | H2 Ebene +2 | 1205Fen0000280895 | m² | 0 | Fensterarbeiten | Fensteröffnung | 0 | 7.5 | NEW | 1205Wa 0000180846 | 0 | - | 0,51 | AllplanAttributes - ash D_Detailverweis: <undefiniert>; U-Wert: 0.9; Schallschutzklasse: 32; Sonnenschutztyp: Movable
Fensteröffnung | H2 Ebene +2 | 1205Fen0000281147 | m² | 0 | Fensterarbeiten | Fensteröffnung | 0 | 7.5 | NEW | 1205Wa 0000180846 | 0 | - | 0,51 | AllplanAttributes - ash D_Detailverweis: <undefiniert>; U-Wert: 0.9; Schallschutzklasse: 32; Sonnenschutztyp: Movable
Türöffnung | H2 Ebene +2 | 1205Tür0000279879 | m² |  | Trockenbauarbeiten | Türöffnung |  | 7.5 | NEW | 1205Wa 0000183508 | 0 | - | 0,51 | AllplanAttributes - ash D_Detailverweis: <undefiniert>; U-Wert: 0.9; Schallschutzklasse: 32; Sonnenschutztyp: Movable; Codetext: Codetext; Türanschlag: DIN L; Pset_OpeningElementCommon - FireExit: no; Reference: Codetext
Türöffnung | H2 Ebene +2 | 1205Tür0000279887 | m³ | 0 | Trockenbauarbeiten | Türöffnung | 0 | 7.5 | NEW | 1205Wa 0000183507 | 0 | - | 0,51 | AllplanAttributes - ash D_Detailverweis: <undefiniert>; U-Wert: 0.9; Schallschutzklasse: 32; Sonnenschutztyp: Movable; Türanschlag: DIN L
Türöffnung | H2 Ebene +2 | 1205Tür0000279877 | m³ | 0 | Trockenbauarbeiten | Türöffnung | 0 | 7.5 | NEW | 1205Wa 0000183506 | 0 | - | 0,51 | AllplanAttributes - ash D_Detailverweis: <undefiniert>; U-Wert: 0.9; Schallschutzklasse: 32; Sonnenschutztyp: Movable; Türanschlag: DIN L
Türöffnung | H2 Ebene +2 | 1205Tür0000279881 | m² | 0 | Trockenbauarbeiten | Türöffnung | 0 | 7.5 | NEW | 1205Wa 0000183505 | 0 | - | 0,51 | AllplanAttributes - ash D_Detailverweis: <undefiniert>; U-Wert: 0.9; Schallschutzklasse: 32; Sonnenschutztyp: Movable; Türanschlag: DIN L
Türöffnung | H2 Ebene +2 | 1205Tür0000279875 | m² | 0 | Trockenbauarbeiten | Türöffnung | 0 | 7.5 | NEW | 1205Wa 0000183504 | 0 | - | 0,51 | AllplanAttributes - ash D_Detailverweis: <undefiniert>; U-Wert: 0.9; Schallschutzklasse: 32; Sonnenschutztyp: Movable; Türanschlag: DIN L
Türöffnung | H2 Ebene +2 | 1205Tür0000279885 | m² | 0 | Trockenbauarbeiten | Türöffnung | 0 | 7.5 | NEW | 1205Wa 0000183503 | 0 | - | 0,51 | AllplanAttributes - ash D_Detailverweis: <undefiniert>; U-Wert: 0.9; Schallschutzklasse: 32; Sonnenschutztyp: Movable; Türanschlag: DIN L
Türöffnung | H2 Ebene +2 | 1205Tür0000279883 | m² | 0 | Trockenbauarbeiten | Türöffnung | 0 | 7.5 | NEW | 1205Wa 0000183502 | 0 | - | 0,51 | AllplanAttributes - ash D_Detailverweis: <undefiniert>; U-Wert: 0.9; Schallschutzklasse: 32; Sonnenschutztyp: Movable; Türanschlag: DIN L
Fensteröffnung | H2 Ebene +2 | 1205Fen0000280289 | m² | 0 | Fensterarbeiten | Fensteröffnung | 0 | 7.5 |  | 1205Wa 0000005300 | 0 | - | 0,51 | AllplanAttributes - ash D_Detailverweis: <undefiniert>; U-Wert: 0.9; Schallschutzklasse: 32; Sonnenschutztyp: Movable
Fensteröffnung | H2 Ebene +2 | 1205Fen0000280115 | m² | 0 | Fensterarbeiten | Fensteröffnung | 0 | 7.5 |  | 1205Wa 0000005300 | 0 | - | 0,51 | AllplanAttributes - ash D_Detailverweis: <undefiniert>; U-Wert: 0.9; Schallschutzklasse: 32; Sonnenschutztyp: Movable
Fensteröffnung | H2 Ebene +2 | 1205Fen0000280223 | m² | 0 | Fensterarbeiten | Fensteröffnung | 0 | 7.5 |  | 1205Wa 0000005300 | 0 | - | 0,51 | AllplanAttributes - ash D_Detailverweis: <undefiniert>; U-Wert: 0.9; Schallschutzklasse: 32; Sonnenschutztyp: Movable
Fensteröffnung | H2 Ebene +2 | 1205Fen0000280151 | m² | 0 | Fensterarbeiten | Fensteröffnung | 0 | 7.5 |  | 1205Wa 0000005300 | 0 | - | 0,51 | AllplanAttributes - ash D_Detailverweis: <undefiniert>; U-Wert: 0.9; Schallschutzklasse: 32; Sonnenschutztyp: Movable
Fensteröffnung | H2 Ebene +2 | 1205Fen2005825952 | m² | 0 | Fensterarbeiten | Fensteröffnung | 0 | 7.5 |  | 1205Wa 0000003947 | 0 | - | 0,51 | AllplanAttributes - ash D_Detailverweis: <undefiniert>; U-Wert: 0.9; Schallschutzklasse: 32; Sonnenschutztyp: Movable
Fensteröffnung | H2 Ebene +2 | 1205Fen0000280665 | m³ | 0 | Fensterarbeiten | Fensteröffnung | 0 | 7.5 |  | 1205Wa 0000005290 | 0 | - | 0,51 | AllplanAttributes - ash D_Detailverweis: <undefiniert>; U-Wert: 0.9; Schallschutzklasse: 32; Sonnenschutztyp: Movable
Fensteröffnung | H2 Ebene +2 | 1205Fen0000281183 | m³ | 0 | Fensterarbeiten | Fensteröffnung | 0 | 7.5 |  | 1205Wa 0000005290 | 0 | - | 0,51 | AllplanAttributes - ash D_Detailverweis: <undefiniert>; U-Wert: 0.9; Schallschutzklasse: 32; Sonnenschutztyp: Movable
Fensteröffnung | H2 Ebene +2 | 1205Fen2005825951 | m³ | 0 | Fensterarbeiten | Fensteröffnung | 0 | 7.5 |  | 1205Wa 0000003957 | 0 | - | 0,51 | AllplanAttributes - ash D_Detailverweis: <undefiniert>; U-Wert: 0.9; Schallschutzklasse: 32; Sonnenschutztyp: Movable
Fensteröffnung | H2 Ebene +2 | 1205Fen0000280835 | m³ | 0 | Fensterarbeiten | Fensteröffnung | 0 | 7.5 |  | 1205Wa 0000005290 | 0 | - | 0,51 | AllplanAttributes - ash D_Detailverweis: <undefiniert>; U-Wert: 0.9; Schallschutzklasse: 32; Sonnenschutztyp: Movable
Fensteröffnung | H2 Ebene +2 | 1205Fen0000280811 | m³ | 0 | Fensterarbeiten | Fensteröffnung | 0 | 7.5 |  | 1205Wa 0000005290 | 0 | - | 0,51 | AllplanAttributes - ash D_Detailverweis: <undefiniert>; U-Wert: 0.9; Schallschutzklasse: 32; Sonnenschutztyp: Movable
Fensteröffnung | H2 Ebene +2 | 1205Fen0000281233 | m³ | 0 | Fensterarbeiten | Fensteröffnung | 0 | 7.5 |  | 1205Wa 0000005280 | 0 | - | 0,51 | AllplanAttributes - ash D_Detailverweis: <undefiniert>; U-Wert: 0.9; Schallschutzklasse: 32; Sonnenschutztyp: Movable
Fensteröffnung | H2 Ebene +2 | 1205Fen0000280545 | m³ | 0 | Fensterarbeiten | Fensteröffnung | 0 | 7.5 |  | 1205Wa 0000005280 | 0 | - | 0,51 | AllplanAttributes - ash D_Detailverweis: <undefiniert>; U-Wert: 0.9; Schallschutzklasse: 32; Sonnenschutztyp: Movable
Fensteröffnung | H2 Ebene +2 | 1205Fen2005825950 | m³ | 0 | Fensterarbeiten | Fensteröffnung | 0 | 7.5 |  | 1205Wa 0000003966 | 0 | - | 0,51 | AllplanAttributes - ash D_Detailverweis: <undefiniert>; U-Wert: 0.9; Schallschutzklasse: 32; Sonnenschutztyp: Movable
Fensteröffnung | H2 Ebene +2 | 1205Fen0000280871 | m³ | 0 | Fensterarbeiten | Fensteröffnung | 0 | 7.5 |  | 1205Wa 0000005280 | 0 | - | 0,51 | AllplanAttributes - ash D_Detailverweis: <undefiniert>; U-Wert: 0.9; Schallschutzklasse: 32; Sonnenschutztyp: Movable
Fensteröffnung | H2 Ebene +2 | 1205Fen0000280831 | m³ | 0 | Fensterarbeiten | Fensteröffnung | 0 | 7.5 |  | 1205Wa 0000005280 | 0 | - | 0,51 | AllplanAttributes - ash D_Detailverweis: <undefiniert>; U-Wert: 0.9; Schallschutzklasse: 32; Sonnenschutztyp: Movable
Fensteröffnung | H2 Ebene +2 | 1205Fen0000280525 | m² | 0 | Fensterarbeiten | Fensteröffnung | 0 | 7.5 |  | 1205Wa 0000005270 | 0 | - | 0,51 | AllplanAttributes - ash D_Detailverweis: <undefiniert>; U-Wert: 0.9; Schallschutzklasse: 32; Sonnenschutztyp: Movable
Fensteröffnung | H2 Ebene +2 | 1205Fen0000280889 | m² | 0 | Fensterarbeiten | Fensteröffnung | 0 | 7.5 |  | 1205Wa 0000005270 | 0 | - | 0,51 | AllplanAttributes - ash D_Detailverweis: <undefiniert>; U-Wert: 0.9; Schallschutzklasse: 32; Sonnenschutztyp: Movable
Fensteröffnung | H2 Ebene +2 | 1205Fen2005825949 | m² | 0 | Fensterarbeiten | Fensteröffnung | 0 | 7.5 |  | 1205Wa 0000003976 | 0 | - | 0,51 | AllplanAttributes - ash D_Detailverweis: <undefiniert>; U-Wert: 0.9; Schallschutzklasse: 32; Sonnenschutztyp: Movable
Fensteröffnung | H2 Ebene +2 | 1205Fen0000280805 | m² | 0 | Fensterarbeiten | Fensteröffnung | 0 | 7.5 |  | 1205Wa 0000005270 | 0 | - | 0,51 | AllplanAttributes - ash D_Detailverweis: <undefiniert>; U-Wert: 0.9; Schallschutzklasse: 32; Sonnenschutztyp: Movable
Fensteröffnung | H2 Ebene +2 | 1205Fen0000281195 | m² | 0 | Fensterarbeiten | Fensteröffnung | 0 | 7.5 |  | 1205Wa 0000005270 | 0 | - | 0,51 | AllplanAttributes - ash D_Detailverweis: <undefiniert>; U-Wert: 0.9; Schallschutzklasse: 32; Sonnenschutztyp: Movable
Fensteröffnung | H2 Ebene +2 | 1205Fen0000280817 | m² | 0 | Fensterarbeiten | Fensteröffnung | 0 | 7.5 | NEW | 1205Wa 0000005260 | 0 | - | 0,51 | AllplanAttributes - ash D_Detailverweis: <undefiniert>; U-Wert: 0.9; Schallschutzklasse: 32; Sonnenschutztyp: Movable
Fensteröffnung | H2 Ebene +2 | 1205Fen0000280759 | m² | 0 | Fensterarbeiten | Fensteröffnung | 0 | 7.5 | NEW | 1205Wa 0000005260 | 0 | - | 0,51 | AllplanAttributes - ash D_Detailverweis: <undefiniert>; U-Wert: 0.9; Schallschutzklasse: 32; Sonnenschutztyp: Movable
Fensteröffnung | H2 Ebene +2 | 1205Fen2005825948 | m² | 0 | Fensterarbeiten | Fensteröffnung | 0 | 7.5 | NEW | 1205Wa 0000003986 | 0 | - | 0,51 | AllplanAttributes - ash D_Detailverweis: <undefiniert>; U-Wert: 0.9; Schallschutzklasse: 32; Sonnenschutztyp: Movable
Fensteröffnung | H2 Ebene +2 | 1205Fen0000280645 | m² | 0 | Fensterarbeiten | Fensteröffnung | 0 | 7.5 | NEW | 1205Wa 0000005260 | 0 | - | 0,51 | AllplanAttributes - ash D_Detailverweis: <undefiniert>; U-Wert: 0.9; Schallschutzklasse: 32; Sonnenschutztyp: Movable
Fensteröffnung | H2 Ebene +2 | 1205Fen0000281061 | m² | 0 | Fensterarbeiten | Fensteröffnung | 0 | 7.5 | NEW | 1205Wa 0000005260 | 0 | - | 0,51 | AllplanAttributes - ash D_Detailverweis: <undefiniert>; U-Wert: 0.9; Schallschutzklasse: 32; Sonnenschutztyp: Movable
Fensteröffnung | H2 Ebene +2 | 1205Fen0000280633 | m² | 0 | Fensterarbeiten | Fensteröffnung | 0 | 7.5 | NEW | 1205Wa 0000005250 | 0 | - | 0,51 | AllplanAttributes - ash D_Detailverweis: <undefiniert>; U-Wert: 0.9; Schallschutzklasse: 32; Sonnenschutztyp: Movable
Fensteröffnung | H2 Ebene +2 | 1205Fen0000280745 | m² | 0 | Fensterarbeiten | Fensteröffnung | 0 | 7.5 | NEW | 1205Wa 0000005250 | 0 | - | 0,51 | AllplanAttributes - ash D_Detailverweis: <undefiniert>; U-Wert: 0.9; Schallschutzklasse: 32; Sonnenschutztyp: Movable
Fensteröffnung | H2 Ebene +2 | 1205Fen2005825947 | m² | 0 | Fensterarbeiten | Fensteröffnung | 0 | 7.5 | NEW | 1205Wa 0000003996 | 0 | - | 0,51 | AllplanAttributes - ash D_Detailverweis: <undefiniert>; U-Wert: 0.9; Schallschutzklasse: 32; Sonnenschutztyp: Movable
Fensteröffnung | H2 Ebene +2 | 1205Fen0000280427 | m² | 0 | Fensterarbeiten | Fensteröffnung | 0 | 7.5 | NEW | 1205Wa 0000005250 | 0 | - | 0,51 | AllplanAttributes - ash D_Detailverweis: <undefiniert>; U-Wert: 0.9; Schallschutzklasse: 32; Sonnenschutztyp: Movable
Fensteröffnung | H2 Ebene +2 | 1205Fen0000281075 | m² | 0 | Fensterarbeiten | Fensteröffnung | 0 | 7.5 | NEW | 1205Wa 0000005250 | 0 | - | 0,51 | AllplanAttributes - ash D_Detailverweis: <undefiniert>; U-Wert: 0.9; Schallschutzklasse: 32; Sonnenschutztyp: Movable
Fensteröffnung | H2 Ebene +2 | 1205Fen0000280747 | m² | 0 | Fensterarbeiten | Fensteröffnung | 0 | 7.5 | NEW | 1205Wa 0000005240 | 0 | - | 0,51 | AllplanAttributes - ash D_Detailverweis: <undefiniert>; U-Wert: 0.9; Schallschutzklasse: 32; Sonnenschutztyp: Movable
Fensteröffnung | H2 Ebene +2 | 1205Fen0000280585 | m² | 0 | Fensterarbeiten | Fensteröffnung | 0 | 7.5 | NEW | 1205Wa 0000005240 | 0 | - | 0,51 | AllplanAttributes - ash D_Detailverweis: <undefiniert>; U-Wert: 0.9; Schallschutzklasse: 32; Sonnenschutztyp: Movable
Fensteröffnung | H2 Ebene +2 | 1205Fen2005825946 | m² | 0 | Fensterarbeiten | Fensteröffnung | 0 | 7.5 | NEW | 1205Wa 0000004006 | 0 | - | 0,51 | AllplanAttributes - ash D_Detailverweis: <undefiniert>; U-Wert: 0.9; Schallschutzklasse: 32; Sonnenschutztyp: Movable
Fensteröffnung | H2 Ebene +2 | 1205Fen0000280671 | m² | 0 | Fensterarbeiten | Fensteröffnung | 0 | 7.5 | NEW | 1205Wa 0000005240 | 0 | - | 0,51 | AllplanAttributes - ash D_Detailverweis: <undefiniert>; U-Wert: 0.9; Schallschutzklasse: 32; Sonnenschutztyp: Movable
Fensteröffnung | H2 Ebene +2 | 1205Fen0000280721 | m² | 0 | Fensterarbeiten | Fensteröffnung | 0 | 7.5 | NEW | 1205Wa 0000005240 | 0 | - | 0,51 | AllplanAttributes - ash D_Detailverweis: <undefiniert>; U-Wert: 0.9; Schallschutzklasse: 32; Sonnenschutztyp: Movable
Fensteröffnung | H2 Ebene +2 | 1205Fen0000279824 | m² |  | Fensterarbeiten | Fensteröffnung |  | 7.5 |  | 1205Wa 0000182626 | 0 | - | 0,51 | AllplanAttributes - ash D_Detailverweis: <undefiniert>; U-Wert: 0.9; Schallschutzklasse: 32; Sonnenschutztyp: Movable
Fensteröffnung | H2 Ebene +2 | 1205Fen0000279826 | m² |  | Fensterarbeiten | Fensteröffnung |  | 7.5 |  | 1205Wa 0000182626 | 0 | - | 0,51 | AllplanAttributes - ash D_Detailverweis: <undefiniert>; U-Wert: 0.9; Schallschutzklasse: 32; Sonnenschutztyp: Movable
Fensteröffnung | H2 Ebene +2 | 1205Fen0000279828 | m² |  | Fensterarbeiten | Fensteröffnung |  | 7.5 |  | 1205Wa 0000182626 | 0 | - | 0,51 | AllplanAttributes - ash D_Detailverweis: <undefiniert>; U-Wert: 0.9; Schallschutzklasse: 32; Sonnenschutztyp: Movable
Fensteröffnung | H2 Ebene +2 | 1205Fen0000279830 | m² |  | Fensterarbeiten | Fensteröffnung |  | 7.5 |  | 1205Wa 0000182626 | 0 | - | 0,51 | AllplanAttributes - ash D_Detailverweis: <undefiniert>; U-Wert: 0.9; Schallschutzklasse: 32; Sonnenschutztyp: Movable
Fensteröffnung | H2 Ebene +2 | 1205Fen0000279818 | m³ | 0 | Fensterarbeiten | Fensteröffnung | 0 | 7.5 |  | 1205Wa 0000182625 | 0 | - | 0,51 | AllplanAttributes - ash D_Detailverweis: <undefiniert>; U-Wert: 0.9; Schallschutzklasse: 32; Sonnenschutztyp: Movable
Fensteröffnung | H2 Ebene +2 | 1205Fen0000279780 | m³ | 0 | Fensterarbeiten | Fensteröffnung | 0 | 7.5 |  | 1205Wa 0000182625 | 0 | - | 0,51 | AllplanAttributes - ash D_Detailverweis: <undefiniert>; U-Wert: 0.9; Schallschutzklasse: 32; Sonnenschutztyp: Movable
Fensteröffnung | H2 Ebene +2 | 1205Fen0000279786 | m³ | 0 | Fensterarbeiten | Fensteröffnung | 0 | 7.5 |  | 1205Wa 0000182625 | 0 | - | 0,51 | AllplanAttributes - ash D_Detailverweis: <undefiniert>; U-Wert: 0.9; Schallschutzklasse: 32; Sonnenschutztyp: Movable
Fensteröffnung | H2 Ebene +2 | 1205Fen0000279776 | m³ | 0 | Fensterarbeiten | Fensteröffnung | 0 | 7.5 |  | 1205Wa 0000182625 | 0 | - | 0,51 | AllplanAttributes - ash D_Detailverweis: <undefiniert>; U-Wert: 0.9; Schallschutzklasse: 32; Sonnenschutztyp: Movable
Fensteröffnung | H2 Ebene +2 | 1205Fen0000279782 | m³ | 0 | Fensterarbeiten | Fensteröffnung | 0 | 7.5 |  | 1205Wa 0000182624 | 0 | - | 0,51 | AllplanAttributes - ash D_Detailverweis: <undefiniert>; U-Wert: 0.9; Schallschutzklasse: 32; Sonnenschutztyp: Movable
Fensteröffnung | H2 Ebene +2 | 1205Fen0000279804 | m³ | 0 | Fensterarbeiten | Fensteröffnung | 0 | 7.5 |  | 1205Wa 0000182624 | 0 | - | 0,51 | AllplanAttributes - ash D_Detailverweis: <undefiniert>; U-Wert: 0.9; Schallschutzklasse: 32; Sonnenschutztyp: Movable
Fensteröffnung | H2 Ebene +2 | 1205Fen0000279798 | m³ | 0 | Fensterarbeiten | Fensteröffnung | 0 | 7.5 |  | 1205Wa 0000182624 | 0 | - | 0,51 | AllplanAttributes - ash D_Detailverweis: <undefiniert>; U-Wert: 0.9; Schallschutzklasse: 32; Sonnenschutztyp: Movable
Fensteröffnung | H2 Ebene +2 | 1205Fen0000279790 | m³ | 0 | Fensterarbeiten | Fensteröffnung | 0 | 7.5 |  | 1205Wa 0000182624 | 0 | - | 0,51 | AllplanAttributes - ash D_Detailverweis: <undefiniert>; U-Wert: 0.9; Schallschutzklasse: 32; Sonnenschutztyp: Movable
Fensteröffnung | H2 Ebene +2 | 1205Fen0000279784 | m² | 0 | Fensterarbeiten | Fensteröffnung | 0 | 7.5 |  | 1205Wa 0000182623 | 0 | - | 0,51 | AllplanAttributes - ash D_Detailverweis: <undefiniert>; U-Wert: 0.9; Schallschutzklasse: 32; Sonnenschutztyp: Movable
Fensteröffnung | H2 Ebene +2 | 1205Fen0000279812 | m² | 0 | Fensterarbeiten | Fensteröffnung | 0 | 7.5 |  | 1205Wa 0000182623 | 0 | - | 0,51 | AllplanAttributes - ash D_Detailverweis: <undefiniert>; U-Wert: 0.9; Schallschutzklasse: 32; Sonnenschutztyp: Movable
Fensteröffnung | H2 Ebene +2 | 1205Fen0000279796 | m² | 0 | Fensterarbeiten | Fensteröffnung | 0 | 7.5 |  | 1205Wa 0000182623 | 0 | - | 0,51 | AllplanAttributes - ash D_Detailverweis: <undefiniert>; U-Wert: 0.9; Schallschutzklasse: 32; Sonnenschutztyp: Movable
Fensteröffnung | H2 Ebene +2 | 1205Fen0000279800 | m² | 0 | Fensterarbeiten | Fensteröffnung | 0 | 7.5 |  | 1205Wa 0000182623 | 0 | - | 0,51 | AllplanAttributes - ash D_Detailverweis: <undefiniert>; U-Wert: 0.9; Schallschutzklasse: 32; Sonnenschutztyp: Movable
Fensteröffnung | H2 Ebene +2 | 1205Fen0000279806 | m² | 0 | Fensterarbeiten | Fensteröffnung | 0 | 7.5 | NEW | 1205Wa 0000182622 | 0 | - | 0,51 | AllplanAttributes - ash D_Detailverweis: <undefiniert>; U-Wert: 0.9; Schallschutzklasse: 32; Sonnenschutztyp: Movable
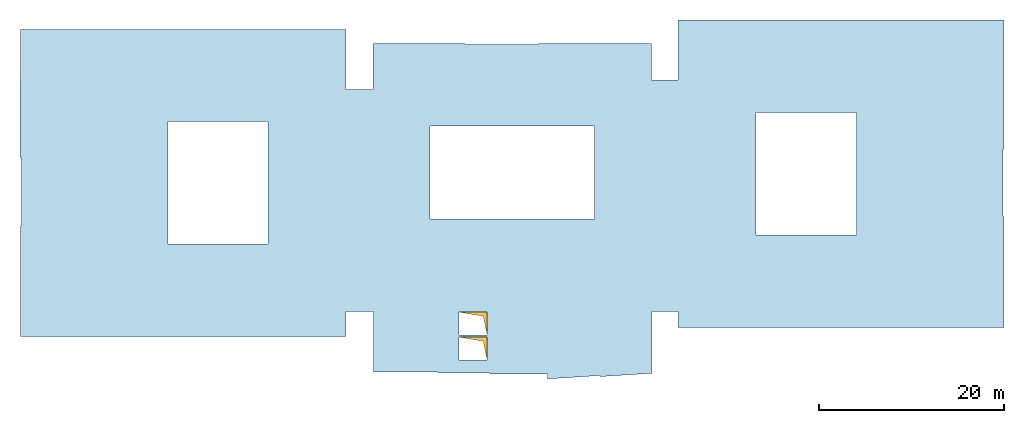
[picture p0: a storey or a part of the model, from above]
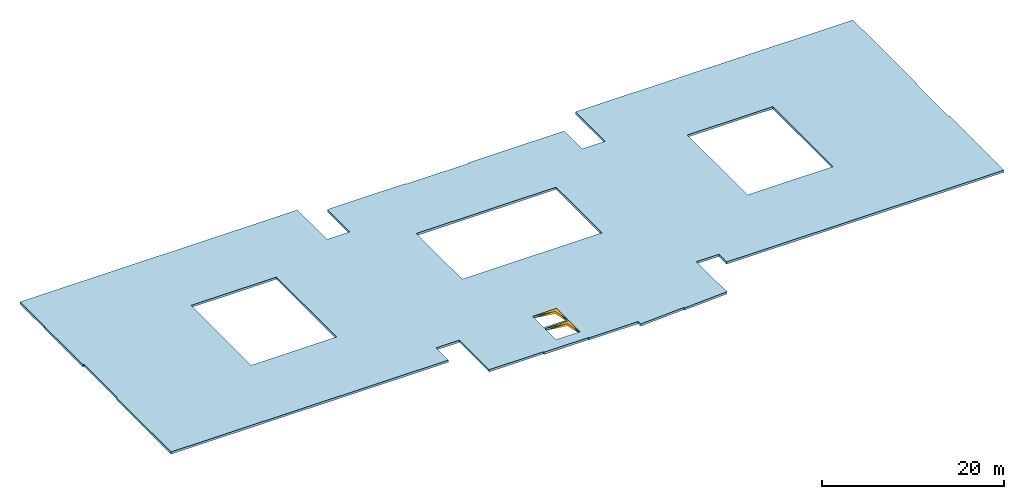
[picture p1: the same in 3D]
Properties of the parts of a building model (IFC4), part 32 of 80

# IfcOpeningElement: Opening (3497)
Name | In | Allright_Bauteil_ID | Abrechnungsart | Versatz_oben | Gewerk | Objektname | Versatz_unten | OKFF | Status | P_ID | AllplanAttributes, Feuerwiderstandsklasse | Sicherheitsklasse | g-Wert
Fensteröffnung | H2 Ebene +2 | 1205Fen0000279778 | m² | 0 | Fensterarbeiten | Fensteröffnung | 0 | 7.5 | NEW | 1205Wa 0000182622 | 0 | - | 0,51 | AllplanAttributes - ash D_Detailverweis: <undefiniert>; U-Wert: 0.9; Schallschutzklasse: 32; Sonnenschutztyp: Movable
Fensteröffnung | H2 Ebene +2 | 1205Fen0000279814 | m² | 0 | Fensterarbeiten | Fensteröffnung | 0 | 7.5 | NEW | 1205Wa 0000182622 | 0 | - | 0,51 | AllplanAttributes - ash D_Detailverweis: <undefiniert>; U-Wert: 0.9; Schallschutzklasse: 32; Sonnenschutztyp: Movable
Fensteröffnung | H2 Ebene +2 | 1205Fen0000279788 | m² | 0 | Fensterarbeiten | Fensteröffnung | 0 | 7.5 | NEW | 1205Wa 0000182622 | 0 | - | 0,51 | AllplanAttributes - ash D_Detailverweis: <undefiniert>; U-Wert: 0.9; Schallschutzklasse: 32; Sonnenschutztyp: Movable
Fensteröffnung | H2 Ebene +2 | 1205Fen0000279808 | m² | 0 | Fensterarbeiten | Fensteröffnung | 0 | 7.5 | NEW | 1205Wa 0000182621 | 0 | - | 0,51 | AllplanAttributes - ash D_Detailverweis: <undefiniert>; U-Wert: 0.9; Schallschutzklasse: 32; Sonnenschutztyp: Movable
Fensteröffnung | H2 Ebene +2 | 1205Fen0000279794 | m² | 0 | Fensterarbeiten | Fensteröffnung | 0 | 7.5 | NEW | 1205Wa 0000182621 | 0 | - | 0,51 | AllplanAttributes - ash D_Detailverweis: <undefiniert>; U-Wert: 0.9; Schallschutzklasse: 32; Sonnenschutztyp: Movable
Fensteröffnung | H2 Ebene +2 | 1205Fen0000279792 | m² | 0 | Fensterarbeiten | Fensteröffnung | 0 | 7.5 | NEW | 1205Wa 0000182621 | 0 | - | 0,51 | AllplanAttributes - ash D_Detailverweis: <undefiniert>; U-Wert: 0.9; Schallschutzklasse: 32; Sonnenschutztyp: Movable
Fensteröffnung | H2 Ebene +2 | 1205Fen0000279822 | m² | 0 | Fensterarbeiten | Fensteröffnung | 0 | 7.5 | NEW | 1205Wa 0000182621 | 0 | - | 0,51 | AllplanAttributes - ash D_Detailverweis: <undefiniert>; U-Wert: 0.9; Schallschutzklasse: 32; Sonnenschutztyp: Movable
Fensteröffnung | H2 Ebene +2 | 1205Fen0000279802 | m² | 0 | Fensterarbeiten | Fensteröffnung | 0 | 7.5 | NEW | 1205Wa 0000182620 | 0 | - | 0,51 | AllplanAttributes - ash D_Detailverweis: <undefiniert>; U-Wert: 0.9; Schallschutzklasse: 32; Sonnenschutztyp: Movable
Fensteröffnung | H2 Ebene +2 | 1205Fen0000279820 | m² | 0 | Fensterarbeiten | Fensteröffnung | 0 | 7.5 | NEW | 1205Wa 0000182620 | 0 | - | 0,51 | AllplanAttributes - ash D_Detailverweis: <undefiniert>; U-Wert: 0.9; Schallschutzklasse: 32; Sonnenschutztyp: Movable
Fensteröffnung | H2 Ebene +2 | 1205Fen0000279810 | m² | 0 | Fensterarbeiten | Fensteröffnung | 0 | 7.5 | NEW | 1205Wa 0000182620 | 0 | - | 0,51 | AllplanAttributes - ash D_Detailverweis: <undefiniert>; U-Wert: 0.9; Schallschutzklasse: 32; Sonnenschutztyp: Movable
Fensteröffnung | H2 Ebene +2 | 1205Fen0000279816 | m² | 0 | Fensterarbeiten | Fensteröffnung | 0 | 7.5 | NEW | 1205Wa 0000182620 | 0 | - | 0,51 | AllplanAttributes - ash D_Detailverweis: <undefiniert>; U-Wert: 0.9; Schallschutzklasse: 32; Sonnenschutztyp: Movable
Fensteröffnung | H2 Ebene +2 | 1205Fen2005824857 | m² | 0 | Trockenbauarbeiten | Fensteröffnung | 0 | 7.5 |  | 1205Wa 0000004406 | 0 | - | 0,51 | AllplanAttributes - ash D_Detailverweis: <undefiniert>; U-Wert: 0.9; Schallschutzklasse: -; Sonnenschutztyp: Movable
Fensteröffnung | H2 Ebene +2 | 1205Fen2005824856 | m² | 0 | Fensterarbeiten | Fensteröffnung | 0 | 7.5 |  | 1205Wa 0000004410 | 0 | - | 0,51 | AllplanAttributes - ash D_Detailverweis: <undefiniert>; U-Wert: 0.9; Schallschutzklasse: -; Sonnenschutztyp: Movable
Fensteröffnung | H2 Ebene +2 | 1205Fen2005824855 | m³ | 0 | Fensterarbeiten | Fensteröffnung | 0 | 7.5 |  | 1205Wa 0000004402 | 0 | - | 0,51 | AllplanAttributes - ash D_Detailverweis: <undefiniert>; U-Wert: 0.9; Schallschutzklasse: -; Sonnenschutztyp: Movable
Fensteröffnung | H2 Ebene +2 | 1205Fen2005824854 | m² | 0 | Fensterarbeiten | Fensteröffnung | 0 | 7.5 |  | 1205Wa 0000004398 | 0 | - | 0,51 | AllplanAttributes - ash D_Detailverweis: <undefiniert>; U-Wert: 0.9; Schallschutzklasse: -; Sonnenschutztyp: Movable
Fensteröffnung | H2 Ebene +2 | 1205Fen2005824853 | m² | 0 | Fensterarbeiten | Fensteröffnung | 0 | 7.5 | NEW | 1205Wa 0000004394 | 0 | - | 0,51 | AllplanAttributes - ash D_Detailverweis: <undefiniert>; U-Wert: 0.9; Schallschutzklasse: -; Sonnenschutztyp: Movable
Fensteröffnung | H2 Ebene +2 | 1205Fen2005824852 | m³ | 0 | Fensterarbeiten | Fensteröffnung | 0 | 7.5 | NEW | 1205Wa 0000004390 | 0 | - | 0,51 | AllplanAttributes - ash D_Detailverweis: <undefiniert>; U-Wert: 0.9; Schallschutzklasse: -; Sonnenschutztyp: Movable
Fensteröffnung | H2 Ebene +2 | 1205Fen2005824851 | m² | 0 | Fensterarbeiten | Fensteröffnung | 0 | 7.5 | NEW | 1205Wa 0000004416 | 0 | - | 0,51 | AllplanAttributes - ash D_Detailverweis: <undefiniert>; U-Wert: 0.9; Schallschutzklasse: -; Sonnenschutztyp: Movable
Fensteröffnung | H2 Ebene +2 | 1205Fen2005824850 | m² | 0 | Fensterarbeiten | Fensteröffnung | 0 | 7.5 | NEW | 1105Wa 0811580073 | AllplanAttributes - Positionsnummer_Text: U23
Fensteröffnung | H2 Ebene +2 | 1205Fen2005824849 | m² | 0 | Fensterarbeiten | Fensteröffnung | 0 | 7.5 | NEW
Türöffnung | H2 Ebene +2 | 1205Tür0000281291 | m² |  | Trockenbauarbeiten | Türöffnung |  | 7.5 | NEW | 1205Wa 0000002623 | 0 | - | 0,51 | AllplanAttributes - ash D_Detailverweis: <undefiniert>; U-Wert: 0.9; Schallschutzklasse: 32; Sonnenschutztyp: Movable; Codetext: Codetext; Türanschlag: DIN R; Pset_OpeningElementCommon - FireExit: no; Reference: Codetext
Türöffnung | H2 Ebene +2 | 1205Tür0000281263 | m³ | 0 | Trockenbauarbeiten | Türöffnung | 0 | 7.5 | NEW | 1205Wa 0000002619 | 0 | - | 0,51 | AllplanAttributes - ash D_Detailverweis: <undefiniert>; U-Wert: 0.9; Schallschutzklasse: 32; Sonnenschutztyp: Movable; Türanschlag: DIN R
Türöffnung | H2 Ebene +2 | 1205Tür0000281277 | m³ | 0 | Trockenbauarbeiten | Türöffnung | 0 | 7.5 | NEW | 1205Wa 0000002614 | 0 | - | 0,51 | AllplanAttributes - ash D_Detailverweis: <undefiniert>; U-Wert: 0.9; Schallschutzklasse: 32; Sonnenschutztyp: Movable; Türanschlag: DIN R
Türöffnung | H2 Ebene +2 | 1205Tür0000281253 | m² | 0 | Trockenbauarbeiten | Türöffnung | 0 | 7.5 | NEW | 1205Wa 0000002609 | 0 | - | 0,51 | AllplanAttributes - ash D_Detailverweis: <undefiniert>; U-Wert: 0.9; Schallschutzklasse: 32; Sonnenschutztyp: Movable; Türanschlag: DIN R
Türöffnung | H2 Ebene +2 | 1205Tür0000281249 | m² | 0 | Trockenbauarbeiten | Türöffnung | 0 | 7.5 | NEW | 1205Wa 0000002605 | 0 | - | 0,51 | AllplanAttributes - ash D_Detailverweis: <undefiniert>; U-Wert: 0.9; Schallschutzklasse: 32; Sonnenschutztyp: Movable; Türanschlag: DIN R
Türöffnung | H2 Ebene +2 | 1205Tür0000281295 | m² | 0 | Trockenbauarbeiten | Türöffnung | 0 | 7.5 | NEW | 1205Wa 0000002601 | 0 | - | 0,51 | AllplanAttributes - ash D_Detailverweis: <undefiniert>; U-Wert: 0.9; Schallschutzklasse: 32; Sonnenschutztyp: Movable; Türanschlag: DIN R
Türöffnung | H2 Ebene +2 | 1205Tür0000281273 | m² | 0 | Trockenbauarbeiten | Türöffnung | 0 | 7.5 | NEW | 1205Wa 0000002680 | 0 | - | 0,51 | AllplanAttributes - ash D_Detailverweis: <undefiniert>; U-Wert: 0.9; Schallschutzklasse: 32; Sonnenschutztyp: Movable; Türanschlag: DIN R
Fensteröffnung | H2 Ebene +2 | 1205Fen0000279922 | m² |  | Fensterarbeiten | Fensteröffnung |  | 7.5 |  | 1205Wa 0000178541 | 0 | - | 0,51 | AllplanAttributes - ash D_Detailverweis: <undefiniert>; U-Wert: 0.9; Schallschutzklasse: -; Sonnenschutztyp: Movable
Fensteröffnung | H2 Ebene +2 | 1205Fen0000279906 | m² | 0 | Fensterarbeiten | Fensteröffnung | 0 | 7.5 |  | 1205Wa 0000178540 | 0 | - | 0,51 | AllplanAttributes - ash D_Detailverweis: <undefiniert>; U-Wert: 0.9; Schallschutzklasse: -; Sonnenschutztyp: Movable
Fensteröffnung | H2 Ebene +2 | 1205Fen0000279908 | m³ | 0 | Fensterarbeiten | Fensteröffnung | 0 | 7.5 |  | 1205Wa 0000178539 | 0 | - | 0,51 | AllplanAttributes - ash D_Detailverweis: <undefiniert>; U-Wert: 0.9; Schallschutzklasse: -; Sonnenschutztyp: Movable
Fensteröffnung | H2 Ebene +2 | 1205Fen0000279910 | m² | 0 | Fensterarbeiten | Fensteröffnung | 0 | 7.5 |  | 1205Wa 0000178538 | 0 | - | 0,51 | AllplanAttributes - ash D_Detailverweis: <undefiniert>; U-Wert: 0.9; Schallschutzklasse: -; Sonnenschutztyp: Movable
Fensteröffnung | H2 Ebene +2 | 1205Fen0000279912 | m² | 0 | Fensterarbeiten | Fensteröffnung | 0 | 7.5 | NEW | 1205Wa 0000178537 | 0 | - | 0,51 | AllplanAttributes - ash D_Detailverweis: <undefiniert>; U-Wert: 0.9; Schallschutzklasse: -; Sonnenschutztyp: Movable
Fensteröffnung | H2 Ebene +2 | 1205Fen0000279914 | m³ | 0 | Fensterarbeiten | Fensteröffnung | 0 | 7.5 | NEW | 1205Wa 0000178536 | 0 | - | 0,51 | AllplanAttributes - ash D_Detailverweis: <undefiniert>; U-Wert: 0.9; Schallschutzklasse: -; Sonnenschutztyp: Movable
Fensteröffnung | H2 Ebene +2 | 1205Fen0000279916 | m² | 0 | Fensterarbeiten | Fensteröffnung | 0 | 7.5 | NEW | 1205Wa 0000178535 | 0 | - | 0,51 | AllplanAttributes - ash D_Detailverweis: <undefiniert>; U-Wert: 0.9; Schallschutzklasse: -; Sonnenschutztyp: Movable
Fensteröffnung | H2 Ebene +2 | 1205Fen0000279918 | m² | 0 | Fensterarbeiten | Fensteröffnung | 0 | 7.5 | NEW | 1205Wa 0000178534 | AllplanAttributes - ash D_Detailverweis: <undefiniert>
Fensteröffnung | H2 Ebene +2 | 1205Fen0000279920 | m² | 0 | Fensterarbeiten | Fensteröffnung | 0 | 7.5 | NEW | 1205Wa 0000178533 | AllplanAttributes - ash D_Detailverweis: <undefiniert>
Fensteröffnung | H2 Ebene +2 | 1205Fen0000280193 | m² |  | Wärmedämm-Verbundsysteme | Fensteröffnung |  | 7.5 | NEW | 1205Wa 0000001093 | 0 | - | 0,51 | AllplanAttributes - Material: Fensterelement; Tragendes Bauteil: no; Brandabschnittsdefinierendes Bauteil: no; ash D_Detailverweis: <undefiniert>; U-Wert: 0.9; Schallschutzklasse: 35; Sonnenschutztyp: Movable
Fensteröffnung | H2 Ebene +2 | 1205Fen0000280130 | m² |  | Wärmedämm-Verbundsysteme | Fensteröffnung |  | 7.5 | NEW | 1205Wa 0000001093 | 0 | - | 0,51 | AllplanAttributes - Material: Fensterelement; Tragendes Bauteil: no; Brandabschnittsdefinierendes Bauteil: no; ash D_Detailverweis: <undefiniert>; U-Wert: 0.9; Schallschutzklasse: 35; Sonnenschutztyp: Movable
Fensteröffnung | H2 Ebene +2 | 1205Fen0000280737 | m³ | 0 | Wärmedämm-Verbundsysteme | Fensteröffnung | 0 | 7.5 | NEW | 1205Wa 0000001097 | 0 | - | 0,51 | AllplanAttributes - Material: Fensterelement; Außenliegend: yes; ash D_Detailverweis: <undefiniert>; U-Wert: 0.9; Schallschutzklasse: 35; Sonnenschutztyp: Movable
Fensteröffnung | H2 Ebene +2 | 1205Fen0000280791 | m³ | 0 | Wärmedämm-Verbundsysteme | Fensteröffnung | 0 | 7.5 | NEW | 1205Wa 0000001097 | 0 | - | 0,51 | AllplanAttributes - Material: Fensterelement; Außenliegend: yes; ash D_Detailverweis: <undefiniert>; U-Wert: 0.9; Schallschutzklasse: 35; Sonnenschutztyp: Movable
Fensteröffnung | H2 Ebene +2 | 1205Fen0000280729 | m³ | 0 | Wärmedämm-Verbundsysteme | Fensteröffnung | 0 | 7.5 | NEW | 1205Wa 0000001117 | 0 | - | 0,51 | AllplanAttributes - ash D_Detailverweis: <undefiniert>; U-Wert: 0.9; Schallschutzklasse: 35; Sonnenschutztyp: Movable
Fensteröffnung | H2 Ebene +2 | 1205Fen0000280495 | m³ | 0 | Wärmedämm-Verbundsysteme | Fensteröffnung | 0 | 7.5 | NEW | 1205Wa 0000001117 | 0 | - | 0,51 | AllplanAttributes - ash D_Detailverweis: <undefiniert>; U-Wert: 0.9; Schallschutzklasse: 35; Sonnenschutztyp: Movable
Fensteröffnung | H2 Ebene +2 | 1205Fen0000280617 | m² | 0 | Wärmedämm-Verbundsysteme | Fensteröffnung | 0 | 7.5 | NEW | 1205Wa 0000001113 | 0 | - | 0,51 | AllplanAttributes - ash D_Detailverweis: <undefiniert>; U-Wert: 0.9; Schallschutzklasse: 35; Sonnenschutztyp: Movable
Fensteröffnung | H2 Ebene +2 | 1205Fen0000280419 | m² | 0 | Wärmedämm-Verbundsysteme | Fensteröffnung | 0 | 7.5 | NEW | 1205Wa 0000001113 | 0 | - | 0,51 | AllplanAttributes - ash D_Detailverweis: <undefiniert>; U-Wert: 0.9; Schallschutzklasse: 35; Sonnenschutztyp: Movable
Fensteröffnung | H2 Ebene +2 | 1205Fen0000281173 | m² | 0 | Wärmedämm-Verbundsysteme | Fensteröffnung | 0 | 7.5 | NEW | 1205Wa 0000001109 | 0 | - | 0,51 | AllplanAttributes - ash D_Detailverweis: <undefiniert>; U-Wert: 0.9; Schallschutzklasse: 35; Sonnenschutztyp: Movable
Fensteröffnung | H2 Ebene +2 | 1205Fen0000280457 | m² | 0 | Wärmedämm-Verbundsysteme | Fensteröffnung | 0 | 7.5 | NEW | 1205Wa 0000001109 | 0 | - | 0,51 | AllplanAttributes - ash D_Detailverweis: <undefiniert>; U-Wert: 0.9; Schallschutzklasse: 35; Sonnenschutztyp: Movable
Fensteröffnung | H2 Ebene +2 | 1205Fen0000280507 | m² | 0 | Wärmedämm-Verbundsysteme | Fensteröffnung | 0 | 7.5 | NEW | 1205Wa 0000001105 | 0 | - | 0,51 | AllplanAttributes - ash D_Detailverweis: <undefiniert>; U-Wert: 0.9; Schallschutzklasse: 35; Sonnenschutztyp: Movable
Fensteröffnung | H2 Ebene +2 | 1205Fen0000280935 | m² | 0 | Wärmedämm-Verbundsysteme | Fensteröffnung | 0 | 7.5 | NEW | 1205Wa 0000001105 | 0 | - | 0,51 | AllplanAttributes - ash D_Detailverweis: <undefiniert>; U-Wert: 0.9; Schallschutzklasse: 35; Sonnenschutztyp: Movable
Fensteröffnung | H2 Ebene +2 | 1205Fen0000280743 | m² | 0 | Wärmedämm-Verbundsysteme | Fensteröffnung | 0 | 7.5 | NEW | 1205Wa 0000001101 | 0 | - | 0,51 | AllplanAttributes - ash D_Detailverweis: <undefiniert>; U-Wert: 0.9; Schallschutzklasse: 35; Sonnenschutztyp: Movable
Fensteröffnung | H2 Ebene +2 | 1205Fen0000280489 | m² | 0 | Wärmedämm-Verbundsysteme | Fensteröffnung | 0 | 7.5 | NEW | 1205Wa 0000001101 | 0 | - | 0,51 | AllplanAttributes - ash D_Detailverweis: <undefiniert>; U-Wert: 0.9; Schallschutzklasse: 35; Sonnenschutztyp: Movable
Fensteröffnung | H2 Ebene +2 | 1205Fen0000330027 | m² |  | Metallbau-, Schlosserarbeiten | Fensteröffnung |  | 7.5 | NEW
Fensteröffnung | H2 Ebene +2 | 1205Fen0000330028 | m² | 0 | Metallbau-, Schlosserarbeiten | Fensteröffnung | 0 | 7.5 | NEW
Fensteröffnung | H2 Ebene +2 | 1205Fen0000330029 | m² | 0 | Metallbau-, Schlosserarbeiten | Fensteröffnung | 0 | 7.5 | NEW
Fensteröffnung | H2 Ebene +2 | 1205Fen0000330030 | m² | 0 | Metallbau-, Schlosserarbeiten | Fensteröffnung | 0 | 7.5 | NEW
Fensteröffnung | H2 Ebene +2 | 1205Fen0000330031 | m² | 0 | Metallbau-, Schlosserarbeiten | Fensteröffnung | 0 | 7.5 | NEW
Fensteröffnung | H2 Ebene +2 | 1205Fen0000330032 | m² | 0 | Metallbau-, Schlosserarbeiten | Fensteröffnung | 0 | 7.5 | NEW
Fensteröffnung | H2 Ebene +2 | 1205Fen0000329989 | m² |  | Metallbau-, Schlosserarbeiten | Fensteröffnung |  | 7.5 | NEW
Fensteröffnung | H2 Ebene +2 | 1205Fen0000329990 | m² | 0 | Metallbau-, Schlosserarbeiten | Fensteröffnung | 0 | 7.5 | NEW
Fensteröffnung | H2 Ebene +2 | 1205Fen0000332080 | m² |  | Metallbau-, Schlosserarbeiten | Fensteröffnung |  | 7.5 | NEW
Fensteröffnung | H2 Ebene +2 | 1205Fen0000332079 | m² | 0 | Metallbau-, Schlosserarbeiten | Fensteröffnung | 0 | 7.5 | NEW
Fensteröffnung | H2 Ebene +2 | 1205Fen0000332078 | m² | 0 | Metallbau-, Schlosserarbeiten | Fensteröffnung | 0 | 7.5 | NEW
Fensteröffnung | H2 Ebene +2 | 1205Fen0000332066 | m² | 0 | Metallbau-, Schlosserarbeiten | Fensteröffnung | 0 | 7.5 | NEW
Fensteröffnung | H2 Ebene +2 | 1205Fen0000332068 | m² | 0 | Metallbau-, Schlosserarbeiten | Fensteröffnung | 0 | 7.5 | NEW
Fensteröffnung | H2 Ebene +2 | 1205Fen0000332069 | m² | 0 | Metallbau-, Schlosserarbeiten | Fensteröffnung | 0 | 7.5 | NEW
Fensteröffnung | H2 Ebene +2 | 1205Fen0000332076 | m² |  | Metallbau-, Schlosserarbeiten | Fensteröffnung |  | 7.5 | NEW
Fensteröffnung | H2 Ebene +2 | 1205Fen0000332077 | m² | 0 | Metallbau-, Schlosserarbeiten | Fensteröffnung | 0 | 7.5 | NEW
Fensteröffnung | H2 Ebene +2 | 1205Fen0000280253 | m² |  | Betonarbeiten | Fensteröffnung |  | 7.5 | NEW | 1205Wa 0000102227 | 0 | - | 0,51 | AllplanAttributes - ash D_Detailverweis: <undefiniert>; U-Wert: 0.9; Schallschutzklasse: 32; Sonnenschutztyp: Movable
Fensteröffnung | H2 Ebene +2 | 1205Fen0000280265 | m² |  | Fensterarbeiten | Fensteröffnung |  | 7.5 |  | 1205Wa 0000102227 | 0 | - | 0,51 | AllplanAttributes - ash D_Detailverweis: <undefiniert>; U-Wert: 0.9; Schallschutzklasse: 32; Sonnenschutztyp: Movable
Fensteröffnung | H2 Ebene +2 | 1205Fen0000280689 | m³ | 0 | Betonarbeiten | Fensteröffnung | 0 | 7.5 | NEW | 1205Wa 0000102231 | 0 | - | 0,51 | AllplanAttributes - Material: Fensterelement; ash D_Detailverweis: <undefiniert>; U-Wert: 0.9; Schallschutzklasse: 32; Sonnenschutztyp: Movable
Fensteröffnung | H2 Ebene +2 | 1205Fen0000281217 | m³ | 0 | Fensterarbeiten | Fensteröffnung | 0 | 7.5 |  | 1205Wa 0000102231 | 0 | - | 0,51 | AllplanAttributes - ash D_Detailverweis: <undefiniert>; U-Wert: 0.9; Schallschutzklasse: 32; Sonnenschutztyp: Movable
Fensteröffnung | H2 Ebene +2 | 1205Fen0000280971 | m³ | 0 | Betonarbeiten | Fensteröffnung | 0 | 7.5 | NEW | 1205Wa 0000102235 | 0 | - | 0,51 | AllplanAttributes - ash D_Detailverweis: <undefiniert>; U-Wert: 0.9; Schallschutzklasse: 32; Sonnenschutztyp: Movable
Fensteröffnung | H2 Ebene +2 | 1205Fen0000280601 | m³ | 0 | Fensterarbeiten | Fensteröffnung | 0 | 7.5 |  | 1205Wa 0000102235 | 0 | - | 0,51 | AllplanAttributes - ash D_Detailverweis: <undefiniert>; U-Wert: 0.9; Schallschutzklasse: 32; Sonnenschutztyp: Movable
Fensteröffnung | H2 Ebene +2 | 1205Fen0000280687 | m² | 0 | Betonarbeiten | Fensteröffnung | 0 | 7.5 | NEW | 1205Wa 0000102239 | 0 | - | 0,51 | AllplanAttributes - ash D_Detailverweis: <undefiniert>; U-Wert: 0.9; Schallschutzklasse: 32; Sonnenschutztyp: Movable
Fensteröffnung | H2 Ebene +2 | 1205Fen0000280609 | m² | 0 | Fensterarbeiten | Fensteröffnung | 0 | 7.5 |  | 1205Wa 0000102239 | 0 | - | 0,51 | AllplanAttributes - ash D_Detailverweis: <undefiniert>; U-Wert: 0.9; Schallschutzklasse: 32; Sonnenschutztyp: Movable
Fensteröffnung | H2 Ebene +2 | 1205Fen0000280839 | m² | 0 | Betonarbeiten | Fensteröffnung | 0 | 7.5 | NEW | 1205Wa 0000102243 | 0 | - | 0,51 | AllplanAttributes - ash D_Detailverweis: <undefiniert>; U-Wert: 0.9; Schallschutzklasse: 32; Sonnenschutztyp: Movable
Fensteröffnung | H2 Ebene +2 | 1205Fen0000280893 | m² | 0 | Fensterarbeiten | Fensteröffnung | 0 | 7.5 | NEW | 1205Wa 0000102243 | 0 | - | 0,51 | AllplanAttributes - ash D_Detailverweis: <undefiniert>; U-Wert: 0.9; Schallschutzklasse: 32; Sonnenschutztyp: Movable
Fensteröffnung | H2 Ebene +2 | 1205Fen0000280537 | m² | 0 | Betonarbeiten | Fensteröffnung | 0 | 7.5 | NEW | 1205Wa 0000102247 | 0 | - | 0,51 | AllplanAttributes - ash D_Detailverweis: <undefiniert>; U-Wert: 0.9; Schallschutzklasse: 32; Sonnenschutztyp: Movable
Fensteröffnung | H2 Ebene +2 | 1205Fen0000280849 | m² | 0 | Fensterarbeiten | Fensteröffnung | 0 | 7.5 | NEW | 1205Wa 0000102247 | 0 | - | 0,51 | AllplanAttributes - ash D_Detailverweis: <undefiniert>; U-Wert: 0.9; Schallschutzklasse: 32; Sonnenschutztyp: Movable
Fensteröffnung | H2 Ebene +2 | 1205Fen0000280855 | m² | 0 | Betonarbeiten | Fensteröffnung | 0 | 7.5 | NEW | 1205Wa 0000102251 | 0 | - | 0,51 | AllplanAttributes - ash D_Detailverweis: FSE1; ash D_Plannummer: D786; U-Wert: 0.9; Schallschutzklasse: 32; Sonnenschutztyp: Movable
Fensteröffnung | H2 Ebene +2 | 1205Fen0000280575 | m² | 0 | Fensterarbeiten | Fensteröffnung | 0 | 7.5 | NEW | 1205Wa 0000102251 | 0 | - | 0,51 | AllplanAttributes - ash D_Detailverweis: <undefiniert>; U-Wert: 0.9; Schallschutzklasse: 32; Sonnenschutztyp: Movable
Fensteröffnung | H2 Ebene +2 | 1205Fen0000333722 | m² |  | Fensterarbeiten | Fensteröffnung |  | 7.5 |  | 1205Wa 0000001796 | 0 | - | 0,51 | AllplanAttributes - ash D_Detailverweis: <undefiniert>; U-Wert: 0.9; Schallschutzklasse: 32; Sonnenschutztyp: Movable
Fensteröffnung | H2 Ebene +2 | 1205Fen0000333727 | m² | 0 | Fensterarbeiten | Fensteröffnung | 0 | 7.5 |  | 1205Wa 0000001793 | 0 | - | 0,51 | AllplanAttributes - ash D_Detailverweis: <undefiniert>; U-Wert: 0.9; Schallschutzklasse: 32; Sonnenschutztyp: Movable
Fensteröffnung | H2 Ebene +2 | 1205Fen0000333726 | m³ | 0 | Fensterarbeiten | Fensteröffnung | 0 | 7.5 |  | 1205Wa 0000001790 | 0 | - | 0,51 | AllplanAttributes - ash D_Detailverweis: <undefiniert>; U-Wert: 0.9; Schallschutzklasse: 32; Sonnenschutztyp: Movable
Fensteröffnung | H2 Ebene +2 | 1205Fen0000333725 | m³ | 0 | Fensterarbeiten | Fensteröffnung | 0 | 7.5 |  | 1205Wa 0000001786 | 0 | - | 0,51 | AllplanAttributes - ash D_Detailverweis: <undefiniert>; U-Wert: 0.9; Schallschutzklasse: 32; Sonnenschutztyp: Movable
Fensteröffnung | H2 Ebene +2 | 1205Fen0000333724 | m² | 0 | Fensterarbeiten | Fensteröffnung | 0 | 7.5 | NEW | 1205Wa 0000001782 | 0 | - | 0,51 | AllplanAttributes - ash D_Detailverweis: <undefiniert>; U-Wert: 0.9; Schallschutzklasse: 32; Sonnenschutztyp: Movable
Fensteröffnung | H2 Ebene +2 | 1205Fen0000334809 | m² |  | Fensterarbeiten | Fensteröffnung |  | 7.5 |  | 1205Wa 0000180327 | 0 | - | 0,51 | AllplanAttributes - ash D_Detailverweis: <undefiniert>; U-Wert: 0.9; Schallschutzklasse: 32; Sonnenschutztyp: Movable
Fensteröffnung | H2 Ebene +2 | 1205Fen0000334808 | m³ | 0 | Fensterarbeiten | Fensteröffnung | 0 | 7.5 |  | 1205Wa 0000180326 | 0 | - | 0,51 | AllplanAttributes - ash D_Detailverweis: <undefiniert>; U-Wert: 0.9; Schallschutzklasse: 32; Sonnenschutztyp: Movable
Fensteröffnung | H2 Ebene +2 | 1205Fen0000334816 | m³ | 0 | Fensterarbeiten | Fensteröffnung | 0 | 7.5 |  | 1205Wa 0000180325 | 0 | - | 0,51 | AllplanAttributes - ash D_Detailverweis: <undefiniert>; U-Wert: 0.9; Schallschutzklasse: 32; Sonnenschutztyp: Movable
Fensteröffnung | H2 Ebene +2 | 1205Fen0000334815 | m² | 0 | Fensterarbeiten | Fensteröffnung | 0 | 7.5 |  | 1205Wa 0000180324 | 0 | - | 0,51 | AllplanAttributes - ash D_Detailverweis: <undefiniert>; U-Wert: 0.9; Schallschutzklasse: 32; Sonnenschutztyp: Movable
Fensteröffnung | H2 Ebene +2 | 1205Fen0000346988 | m² | 0 | Fensterarbeiten | Fensteröffnung | 0 | 7.5 |  | 1205Wa 0000003947 | 0 | - | 0,51 | AllplanAttributes - ash D_Detailverweis: <undefiniert>; U-Wert: 0.9; Schallschutzklasse: 32; Sonnenschutztyp: Movable
Fensteröffnung | H2 Ebene +2 | 1205Fen0000347139 | m² | 0 | Fensterarbeiten | Fensteröffnung | 0 | 7.5 |  | 1205Wa 0000003947 | 0 | - | 0,51 | AllplanAttributes - ash D_Detailverweis: <undefiniert>; U-Wert: 0.9; Schallschutzklasse: 32; Sonnenschutztyp: Movable
Fensteröffnung | H2 Ebene +2 | 1205Fen0000347228 | m² | 0 | Fensterarbeiten | Fensteröffnung | 0 | 7.5 |  | 1205Wa 0000003947 | 0 | - | 0,51 | AllplanAttributes - ash D_Detailverweis: <undefiniert>; U-Wert: 0.9; Schallschutzklasse: 32; Sonnenschutztyp: Movable
Fensteröffnung | H2 Ebene +2 | 1205Fen0000347317 | m² | 0 | Fensterarbeiten | Fensteröffnung | 0 | 7.5 |  | 1205Wa 0000003947 | 0 | - | 0,51 | AllplanAttributes - ash D_Detailverweis: <undefiniert>; U-Wert: 0.9; Schallschutzklasse: 32; Sonnenschutztyp: Movable
Fensteröffnung | H2 Ebene +2 | 1205Fen0000347227 | m³ | 0 | Fensterarbeiten | Fensteröffnung | 0 | 7.5 |  | 1205Wa 0000003957 | 0 | - | 0,51 | AllplanAttributes - ash D_Detailverweis: <undefiniert>; U-Wert: 0.9; Schallschutzklasse: 32; Sonnenschutztyp: Movable
Fensteröffnung | H2 Ebene +2 | 1205Fen0000347138 | m³ | 0 | Fensterarbeiten | Fensteröffnung | 0 | 7.5 |  | 1205Wa 0000003957 | 0 | - | 0,51 | AllplanAttributes - ash D_Detailverweis: <undefiniert>; U-Wert: 0.9; Schallschutzklasse: 32; Sonnenschutztyp: Movable
Fensteröffnung | H2 Ebene +2 | 1205Fen0000346987 | m³ | 0 | Fensterarbeiten | Fensteröffnung | 0 | 7.5 |  | 1205Wa 0000003957 | 0 | - | 0,51 | AllplanAttributes - ash D_Detailverweis: <undefiniert>; U-Wert: 0.9; Schallschutzklasse: 32; Sonnenschutztyp: Movable
Fensteröffnung | H2 Ebene +2 | 1205Fen0000347316 | m³ | 0 | Fensterarbeiten | Fensteröffnung | 0 | 7.5 |  | 1205Wa 0000003957 | 0 | - | 0,51 | AllplanAttributes - ash D_Detailverweis: <undefiniert>; U-Wert: 0.9; Schallschutzklasse: 32; Sonnenschutztyp: Movable
Fensteröffnung | H2 Ebene +2 | 1205Fen0000347226 | m³ | 0 | Fensterarbeiten | Fensteröffnung | 0 | 7.5 |  | 1205Wa 0000003966 | 0 | - | 0,51 | AllplanAttributes - ash D_Detailverweis: <undefiniert>; U-Wert: 0.9; Schallschutzklasse: 32; Sonnenschutztyp: Movable
Fensteröffnung | H2 Ebene +2 | 1205Fen0000347137 | m³ | 0 | Fensterarbeiten | Fensteröffnung | 0 | 7.5 |  | 1205Wa 0000003966 | 0 | - | 0,51 | AllplanAttributes - ash D_Detailverweis: <undefiniert>; U-Wert: 0.9; Schallschutzklasse: 32; Sonnenschutztyp: Movable
Fensteröffnung | H2 Ebene +2 | 1205Fen0000346986 | m³ | 0 | Fensterarbeiten | Fensteröffnung | 0 | 7.5 |  | 1205Wa 0000003966 | 0 | - | 0,51 | AllplanAttributes - ash D_Detailverweis: <undefiniert>; U-Wert: 0.9; Schallschutzklasse: 32; Sonnenschutztyp: Movable
Fensteröffnung | H2 Ebene +2 | 1205Fen0000347315 | m³ | 0 | Fensterarbeiten | Fensteröffnung | 0 | 7.5 |  | 1205Wa 0000003966 | 0 | - | 0,51 | AllplanAttributes - ash D_Detailverweis: <undefiniert>; U-Wert: 0.9; Schallschutzklasse: 32; Sonnenschutztyp: Movable
Fensteröffnung | H2 Ebene +2 | 1205Fen0000347225 | m³ | 0 | Fensterarbeiten | Fensteröffnung | 0 | 7.5 |  | 1205Wa 0000003976 | 0 | - | 0,51 | AllplanAttributes - ash D_Detailverweis: <undefiniert>; U-Wert: 0.9; Schallschutzklasse: 32; Sonnenschutztyp: Movable
Fensteröffnung | H2 Ebene +2 | 1205Fen0000347136 | m³ | 0 | Fensterarbeiten | Fensteröffnung | 0 | 7.5 |  | 1205Wa 0000003976 | 0 | - | 0,51 | AllplanAttributes - ash D_Detailverweis: <undefiniert>; U-Wert: 0.9; Schallschutzklasse: 32; Sonnenschutztyp: Movable
Fensteröffnung | H2 Ebene +2 | 1205Fen0000346985 | m³ | 0 | Fensterarbeiten | Fensteröffnung | 0 | 7.5 |  | 1205Wa 0000003976 | 0 | - | 0,51 | AllplanAttributes - ash D_Detailverweis: <undefiniert>; U-Wert: 0.9; Schallschutzklasse: 32; Sonnenschutztyp: Movable
Fensteröffnung | H2 Ebene +2 | 1205Fen0000347314 | m³ | 0 | Fensterarbeiten | Fensteröffnung | 0 | 7.5 |  | 1205Wa 0000003976 | 0 | - | 0,51 | AllplanAttributes - ash D_Detailverweis: <undefiniert>; U-Wert: 0.9; Schallschutzklasse: 32; Sonnenschutztyp: Movable
Fensteröffnung | H2 Ebene +2 | 1205Fen0000347224 | m² | 0 | Fensterarbeiten | Fensteröffnung | 0 | 7.5 | NEW | 1205Wa 0000003986 | 0 | - | 0,51 | AllplanAttributes - ash D_Detailverweis: <undefiniert>; U-Wert: 0.9; Schallschutzklasse: 32; Sonnenschutztyp: Movable
Fensteröffnung | H2 Ebene +2 | 1205Fen0000347135 | m² | 0 | Fensterarbeiten | Fensteröffnung | 0 | 7.5 | NEW | 1205Wa 0000003986 | 0 | - | 0,51 | AllplanAttributes - ash D_Detailverweis: <undefiniert>; U-Wert: 0.9; Schallschutzklasse: 32; Sonnenschutztyp: Movable
Fensteröffnung | H2 Ebene +2 | 1205Fen0000346984 | m² | 0 | Fensterarbeiten | Fensteröffnung | 0 | 7.5 | NEW | 1205Wa 0000003986 | 0 | - | 0,51 | AllplanAttributes - ash D_Detailverweis: <undefiniert>; U-Wert: 0.9; Schallschutzklasse: 32; Sonnenschutztyp: Movable
Fensteröffnung | H2 Ebene +2 | 1205Fen0000347313 | m² | 0 | Fensterarbeiten | Fensteröffnung | 0 | 7.5 | NEW | 1205Wa 0000003986 | 0 | - | 0,51 | AllplanAttributes - ash D_Detailverweis: <undefiniert>; U-Wert: 0.9; Schallschutzklasse: 32; Sonnenschutztyp: Movable
Fensteröffnung | H2 Ebene +2 | 1205Fen0000347223 | m² | 0 | Fensterarbeiten | Fensteröffnung | 0 | 7.5 | NEW | 1205Wa 0000003996 | 0 | - | 0,51 | AllplanAttributes - ash D_Detailverweis: <undefiniert>; U-Wert: 0.9; Schallschutzklasse: 32; Sonnenschutztyp: Movable
Fensteröffnung | H2 Ebene +2 | 1205Fen0000347134 | m² | 0 | Fensterarbeiten | Fensteröffnung | 0 | 7.5 | NEW | 1205Wa 0000003996 | 0 | - | 0,51 | AllplanAttributes - ash D_Detailverweis: <undefiniert>; U-Wert: 0.9; Schallschutzklasse: 32; Sonnenschutztyp: Movable
Fensteröffnung | H2 Ebene +2 | 1205Fen0000346983 | m² | 0 | Fensterarbeiten | Fensteröffnung | 0 | 7.5 | NEW | 1205Wa 0000003996 | 0 | - | 0,51 | AllplanAttributes - ash D_Detailverweis: <undefiniert>; U-Wert: 0.9; Schallschutzklasse: 32; Sonnenschutztyp: Movable
Fensteröffnung | H2 Ebene +2 | 1205Fen0000347312 | m² | 0 | Fensterarbeiten | Fensteröffnung | 0 | 7.5 | NEW | 1205Wa 0000003996 | 0 | - | 0,51 | AllplanAttributes - ash D_Detailverweis: <undefiniert>; U-Wert: 0.9; Schallschutzklasse: 32; Sonnenschutztyp: Movable
Fensteröffnung | H2 Ebene +2 | 1205Fen0000347222 | m² | 0 | Fensterarbeiten | Fensteröffnung | 0 | 7.5 | NEW | 1205Wa 0000004006 | 0 | - | 0,51 | AllplanAttributes - ash D_Detailverweis: <undefiniert>; U-Wert: 0.9; Schallschutzklasse: 32; Sonnenschutztyp: Movable
Fensteröffnung | H2 Ebene +2 | 1205Fen0000347133 | m² | 0 | Fensterarbeiten | Fensteröffnung | 0 | 7.5 | NEW | 1205Wa 0000004006 | 0 | - | 0,51 | AllplanAttributes - ash D_Detailverweis: <undefiniert>; U-Wert: 0.9; Schallschutzklasse: 32; Sonnenschutztyp: Movable
Fensteröffnung | H2 Ebene +2 | 1205Fen0000346982 | m² | 0 | Fensterarbeiten | Fensteröffnung | 0 | 7.5 | NEW | 1205Wa 0000004006 | 0 | - | 0,51 | AllplanAttributes - ash D_Detailverweis: <undefiniert>; U-Wert: 0.9; Schallschutzklasse: 32; Sonnenschutztyp: Movable
Fensteröffnung | H2 Ebene +2 | 1205Fen0000347311 | m² | 0 | Fensterarbeiten | Fensteröffnung | 0 | 7.5 | NEW | 1205Wa 0000004006 | 0 | - | 0,51 | AllplanAttributes - ash D_Detailverweis: <undefiniert>; U-Wert: 0.9; Schallschutzklasse: 32; Sonnenschutztyp: Movable
Fensteröffnung | H2 Ebene +2 | 1205Fen0000347221 | m² | 0 | Fensterarbeiten | Fensteröffnung | 0 | 7.5 | NEW | 1105Wa 0811580073 | AllplanAttributes - Positionsnummer_Text: U23
Fensteröffnung | H2 Ebene +2 | 1205Fen0000347132 | m² | 0 | Fensterarbeiten | Fensteröffnung | 0 | 7.5 | NEW | 1105Wa 0811580073 | AllplanAttributes - Positionsnummer_Text: U23
Fensteröffnung | H2 Ebene +2 | 1205Fen0000346981 | m² | 0 | Fensterarbeiten | Fensteröffnung | 0 | 7.5 | NEW | 1105Wa 0811580073 | AllplanAttributes - Positionsnummer_Text: U23
Fensteröffnung | H2 Ebene +2 | 1205Fen0000347310 | m² | 0 | Fensterarbeiten | Fensteröffnung | 0 | 7.5 | NEW | 1105Wa 0811580073 | AllplanAttributes - Positionsnummer_Text: U23
Fensteröffnung | H2 Ebene +2 | 1205Fen2005817138 | m² | 0 | Fensterarbeiten | Fensteröffnung | 0 | 7.5 |  | 1155Wa 0000003947 | 0 | - | 0,51 | AllplanAttributes - U-Wert: 0.9; Schallschutzklasse: 32; Sonnenschutztyp: Movable
Fensteröffnung | H2 Ebene +2 | 1205Fen2005817061 | m² | 0 | Fensterarbeiten | Fensteröffnung | 0 | 7.5 |  | 1155Wa 0000003947 | 0 | - | 0,51 | AllplanAttributes - U-Wert: 0.9; Schallschutzklasse: 32; Sonnenschutztyp: Movable
Fensteröffnung | H2 Ebene +2 | 1205Fen2005816904 | m² | 0 | Fensterarbeiten | Fensteröffnung | 0 | 7.5 |  | 1155Wa 0000003947 | 0 | - | 0,51 | AllplanAttributes - U-Wert: 0.9; Schallschutzklasse: 32; Sonnenschutztyp: Movable
Fensteröffnung | H2 Ebene +2 | 1205Fen0000358291 | m² | 0 | Fensterarbeiten | Fensteröffnung | 0 | 7.5 |  | 1155Wa 0000003947 | 0 | - | 0,51 | AllplanAttributes - U-Wert: 0.9; Schallschutzklasse: 32; Sonnenschutztyp: Movable
Fensteröffnung | H2 Ebene +2 | 1205Fen0000358290 | m³ | 0 | Fensterarbeiten | Fensteröffnung | 0 | 7.5 |  | 1155Wa 0000003957 | 0 | - | 0,51 | AllplanAttributes - U-Wert: 0.9; Schallschutzklasse: 32; Sonnenschutztyp: Movable
Fensteröffnung | H2 Ebene +2 | 1205Fen2005816903 | m³ | 0 | Fensterarbeiten | Fensteröffnung | 0 | 7.5 |  | 1155Wa 0000003957 | 0 | - | 0,51 | AllplanAttributes - U-Wert: 0.9; Schallschutzklasse: 32; Sonnenschutztyp: Movable
Fensteröffnung | H2 Ebene +2 | 1205Fen2005817060 | m³ | 0 | Fensterarbeiten | Fensteröffnung | 0 | 7.5 |  | 1155Wa 0000003957 | 0 | - | 0,51 | AllplanAttributes - U-Wert: 0.9; Schallschutzklasse: 32; Sonnenschutztyp: Movable
Fensteröffnung | H2 Ebene +2 | 1205Fen2005817137 | m³ | 0 | Fensterarbeiten | Fensteröffnung | 0 | 7.5 |  | 1155Wa 0000003957 | 0 | - | 0,51 | AllplanAttributes - U-Wert: 0.9; Schallschutzklasse: 32; Sonnenschutztyp: Movable
Fensteröffnung | H2 Ebene +2 | 1205Fen0000358289 | m³ | 0 | Fensterarbeiten | Fensteröffnung | 0 | 7.5 |  | 1155Wa 0000003966 | 0 | - | 0,51 | AllplanAttributes - U-Wert: 0.9; Schallschutzklasse: 32; Sonnenschutztyp: Movable
Fensteröffnung | H2 Ebene +2 | 1205Fen2005817059 | m³ | 0 | Fensterarbeiten | Fensteröffnung | 0 | 7.5 |  | 1155Wa 0000003966 | 0 | - | 0,51 | AllplanAttributes - U-Wert: 0.9; Schallschutzklasse: 32; Sonnenschutztyp: Movable
Fensteröffnung | H2 Ebene +2 | 1205Fen2005816902 | m³ | 0 | Fensterarbeiten | Fensteröffnung | 0 | 7.5 |  | 1155Wa 0000003966 | 0 | - | 0,51 | AllplanAttributes - U-Wert: 0.9; Schallschutzklasse: 32; Sonnenschutztyp: Movable
Fensteröffnung | H2 Ebene +2 | 1205Fen2005817136 | m³ | 0 | Fensterarbeiten | Fensteröffnung | 0 | 7.5 |  | 1155Wa 0000003966 | 0 | - | 0,51 | AllplanAttributes - U-Wert: 0.9; Schallschutzklasse: 32; Sonnenschutztyp: Movable; Bezeichnung: Fensteröffnung
Fensteröffnung | H2 Ebene +2 | 1205Fen0000358288 | m² | 0 | Fensterarbeiten | Fensteröffnung | 0 | 7.5 |  | 1155Wa 0000003976 | 0 | - | 0,51 | AllplanAttributes - U-Wert: 0.9; Schallschutzklasse: 32; Sonnenschutztyp: Movable
Fensteröffnung | H2 Ebene +2 | 1205Fen2005816901 | m² | 0 | Fensterarbeiten | Fensteröffnung | 0 | 7.5 |  | 1155Wa 0000003976 | 0 | - | 0,51 | AllplanAttributes - U-Wert: 0.9; Schallschutzklasse: 32; Sonnenschutztyp: Movable
Fensteröffnung | H2 Ebene +2 | 1205Fen2005817058 | m² | 0 | Fensterarbeiten | Fensteröffnung | 0 | 7.5 |  | 1155Wa 0000003976 | 0 | - | 0,51 | AllplanAttributes - U-Wert: 0.9; Schallschutzklasse: 32; Sonnenschutztyp: Movable
Fensteröffnung | H2 Ebene +2 | 1205Fen2005817135 | m² | 0 | Fensterarbeiten | Fensteröffnung | 0 | 7.5 |  | 1155Wa 0000003976 | 0 | - | 0,51 | AllplanAttributes - U-Wert: 0.9; Schallschutzklasse: 32; Sonnenschutztyp: Movable
Fensteröffnung | H2 Ebene +2 | 1205Fen0000358287 | m² | 0 | Fensterarbeiten | Fensteröffnung | 0 | 7.5 | NEW | 1155Wa 0000003986 | 0 | - | 0,51 | AllplanAttributes - U-Wert: 0.9; Schallschutzklasse: 32; Sonnenschutztyp: Movable
Fensteröffnung | H2 Ebene +2 | 1205Fen2005816900 | m² | 0 | Fensterarbeiten | Fensteröffnung | 0 | 7.5 | NEW | 1155Wa 0000003986 | 0 | - | 0,51 | AllplanAttributes - U-Wert: 0.9; Schallschutzklasse: 32; Sonnenschutztyp: Movable
Fensteröffnung | H2 Ebene +2 | 1205Fen2005817057 | m² | 0 | Fensterarbeiten | Fensteröffnung | 0 | 7.5 | NEW | 1155Wa 0000003986 | 0 | - | 0,51 | AllplanAttributes - U-Wert: 0.9; Schallschutzklasse: 32; Sonnenschutztyp: Movable
Fensteröffnung | H2 Ebene +2 | 1205Fen2005817134 | m² | 0 | Fensterarbeiten | Fensteröffnung | 0 | 7.5 | NEW | 1155Wa 0000003986 | 0 | - | 0,51 | AllplanAttributes - U-Wert: 0.9; Schallschutzklasse: 32; Sonnenschutztyp: Movable
Fensteröffnung | H2 Ebene +2 | 1205Fen0000358286 | m² | 0 | Fensterarbeiten | Fensteröffnung | 0 | 7.5 | NEW | 1155Wa 0000003996 | 0 | - | 0,51 | AllplanAttributes - U-Wert: 0.9; Schallschutzklasse: 32; Sonnenschutztyp: Movable
Fensteröffnung | H2 Ebene +2 | 1205Fen2005816899 | m² | 0 | Fensterarbeiten | Fensteröffnung | 0 | 7.5 | NEW | 1155Wa 0000003996 | 0 | - | 0,51 | AllplanAttributes - U-Wert: 0.9; Schallschutzklasse: 32; Sonnenschutztyp: Movable
Fensteröffnung | H2 Ebene +2 | 1205Fen2005817056 | m² | 0 | Fensterarbeiten | Fensteröffnung | 0 | 7.5 | NEW | 1155Wa 0000003996 | 0 | - | 0,51 | AllplanAttributes - U-Wert: 0.9; Schallschutzklasse: 32; Sonnenschutztyp: Movable
Fensteröffnung | H2 Ebene +2 | 1205Fen2005817133 | m² | 0 | Fensterarbeiten | Fensteröffnung | 0 | 7.5 | NEW | 1155Wa 0000003996 | 0 | - | 0,51 | AllplanAttributes - U-Wert: 0.9; Schallschutzklasse: 32; Sonnenschutztyp: Movable
Fensteröffnung | H2 Ebene +2 | 1205Fen0000358285 | m² | 0 | Fensterarbeiten | Fensteröffnung | 0 | 7.5 | NEW | 1155Wa 0000004006 | 0 | - | 0,51 | AllplanAttributes - U-Wert: 0.9; Schallschutzklasse: 32; Sonnenschutztyp: Movable
Fensteröffnung | H2 Ebene +2 | 1205Fen2005816898 | m² | 0 | Fensterarbeiten | Fensteröffnung | 0 | 7.5 | NEW | 1155Wa 0000004006 | 0 | - | 0,51 | AllplanAttributes - U-Wert: 0.9; Schallschutzklasse: 32; Sonnenschutztyp: Movable
Fensteröffnung | H2 Ebene +2 | 1205Fen2005817055 | m² | 0 | Fensterarbeiten | Fensteröffnung | 0 | 7.5 | NEW | 1155Wa 0000004006 | 0 | - | 0,51 | AllplanAttributes - U-Wert: 0.9; Schallschutzklasse: 32; Sonnenschutztyp: Movable
Fensteröffnung | H2 Ebene +2 | 1205Fen2005817132 | m² | 0 | Fensterarbeiten | Fensteröffnung | 0 | 7.5 | NEW | 1155Wa 0000004006 | 0 | - | 0,51 | AllplanAttributes - U-Wert: 0.9; Schallschutzklasse: 32; Sonnenschutztyp: Movable
Fensteröffnung | H2 Ebene +2 | 1205Fen2005825855 | m² | 0 | Fensterarbeiten | Fensteröffnung | 0 | 7.5 |  | 1205Wa 0000003947 | 0 | - | 0,51 | AllplanAttributes - ash D_Detailverweis: <undefiniert>; U-Wert: 0.9; Schallschutzklasse: 32; Sonnenschutztyp: Movable
Fensteröffnung | H2 Ebene +2 | 1205Fen2005825773 | m² | 0 | Fensterarbeiten | Fensteröffnung | 0 | 7.5 |  | 1205Wa 0000003947 | 0 | - | 0,51 | AllplanAttributes - ash D_Detailverweis: <undefiniert>; U-Wert: 0.9; Schallschutzklasse: 32; Sonnenschutztyp: Movable
Fensteröffnung | H2 Ebene +2 | 1205Fen2005825691 | m² | 0 | Fensterarbeiten | Fensteröffnung | 0 | 7.5 |  | 1205Wa 0000003947 | 0 | - | 0,51 | AllplanAttributes - ash D_Detailverweis: <undefiniert>; U-Wert: 0.9; Schallschutzklasse: 32; Sonnenschutztyp: Movable
Fensteröffnung | H2 Ebene +2 | 1205Fen2005825463 | m² | 0 | Fensterarbeiten | Fensteröffnung | 0 | 7.5 |  | 1205Wa 0000003947 | 0 | - | 0,51 | AllplanAttributes - ash D_Detailverweis: <undefiniert>; U-Wert: 0.9; Schallschutzklasse: 32; Sonnenschutztyp: Movable
Fensteröffnung | H2 Ebene +2 | 1205Fen2005825854 | m³ | 0 | Fensterarbeiten | Fensteröffnung | 0 | 7.5 |  | 1205Wa 0000003957 | 0 | - | 0,51 | AllplanAttributes - ash D_Detailverweis: <undefiniert>; U-Wert: 0.9; Schallschutzklasse: 32; Sonnenschutztyp: Movable
Fensteröffnung | H2 Ebene +2 | 1205Fen2005825772 | m³ | 0 | Fensterarbeiten | Fensteröffnung | 0 | 7.5 |  | 1205Wa 0000003957 | 0 | - | 0,51 | AllplanAttributes - ash D_Detailverweis: <undefiniert>; U-Wert: 0.9; Schallschutzklasse: 32; Sonnenschutztyp: Movable
Fensteröffnung | H2 Ebene +2 | 1205Fen2005825690 | m³ | 0 | Fensterarbeiten | Fensteröffnung | 0 | 7.5 |  | 1205Wa 0000003957 | 0 | - | 0,51 | AllplanAttributes - ash D_Detailverweis: <undefiniert>; U-Wert: 0.9; Schallschutzklasse: 32; Sonnenschutztyp: Movable
Fensteröffnung | H2 Ebene +2 | 1205Fen2005825462 | m³ | 0 | Fensterarbeiten | Fensteröffnung | 0 | 7.5 |  | 1205Wa 0000003957 | 0 | - | 0,51 | AllplanAttributes - ash D_Detailverweis: <undefiniert>; U-Wert: 0.9; Schallschutzklasse: 32; Sonnenschutztyp: Movable
Fensteröffnung | H2 Ebene +2 | 1205Fen2005825853 | m³ | 0 | Fensterarbeiten | Fensteröffnung | 0 | 7.5 |  | 1205Wa 0000003966 | 0 | - | 0,51 | AllplanAttributes - ash D_Detailverweis: <undefiniert>; U-Wert: 0.9; Schallschutzklasse: 32; Sonnenschutztyp: Movable
Fensteröffnung | H2 Ebene +2 | 1205Fen2005825771 | m³ | 0 | Fensterarbeiten | Fensteröffnung | 0 | 7.5 |  | 1205Wa 0000003966 | 0 | - | 0,51 | AllplanAttributes - ash D_Detailverweis: <undefiniert>; U-Wert: 0.9; Schallschutzklasse: 32; Sonnenschutztyp: Movable
Fensteröffnung | H2 Ebene +2 | 1205Fen2005825689 | m³ | 0 | Fensterarbeiten | Fensteröffnung | 0 | 7.5 |  | 1205Wa 0000003966 | 0 | - | 0,51 | AllplanAttributes - ash D_Detailverweis: <undefiniert>; U-Wert: 0.9; Schallschutzklasse: 32; Sonnenschutztyp: Movable
Fensteröffnung | H2 Ebene +2 | 1205Fen2005825461 | m³ | 0 | Fensterarbeiten | Fensteröffnung | 0 | 7.5 |  | 1205Wa 0000003966 | 0 | - | 0,51 | AllplanAttributes - ash D_Detailverweis: <undefiniert>; U-Wert: 0.9; Schallschutzklasse: 32; Sonnenschutztyp: Movable
Fensteröffnung | H2 Ebene +2 | 1205Fen2005825852 | m³ | 0 | Fensterarbeiten | Fensteröffnung | 0 | 7.5 |  | 1205Wa 0000003976 | 0 | - | 0,51 | AllplanAttributes - ash D_Detailverweis: <undefiniert>; U-Wert: 0.9; Schallschutzklasse: 32; Sonnenschutztyp: Movable
Fensteröffnung | H2 Ebene +2 | 1205Fen2005825770 | m³ | 0 | Fensterarbeiten | Fensteröffnung | 0 | 7.5 |  | 1205Wa 0000003976 | 0 | - | 0,51 | AllplanAttributes - ash D_Detailverweis: <undefiniert>; U-Wert: 0.9; Schallschutzklasse: 32; Sonnenschutztyp: Movable
Fensteröffnung | H2 Ebene +2 | 1205Fen2005825688 | m³ | 0 | Fensterarbeiten | Fensteröffnung | 0 | 7.5 |  | 1205Wa 0000003976 | 0 | - | 0,51 | AllplanAttributes - ash D_Detailverweis: <undefiniert>; U-Wert: 0.9; Schallschutzklasse: 32; Sonnenschutztyp: Movable
Fensteröffnung | H2 Ebene +2 | 1205Fen2005825460 | m³ | 0 | Fensterarbeiten | Fensteröffnung | 0 | 7.5 |  | 1205Wa 0000003976 | 0 | - | 0,51 | AllplanAttributes - ash D_Detailverweis: <undefiniert>; U-Wert: 0.9; Schallschutzklasse: 32; Sonnenschutztyp: Movable
Fensteröffnung | H2 Ebene +2 | 1205Fen2005825851 | m² | 0 | Fensterarbeiten | Fensteröffnung | 0 | 7.5 | NEW | 1205Wa 0000003986 | 0 | - | 0,51 | AllplanAttributes - ash D_Detailverweis: <undefiniert>; U-Wert: 0.9; Schallschutzklasse: 32; Sonnenschutztyp: Movable
Fensteröffnung | H2 Ebene +2 | 1205Fen2005825769 | m² | 0 | Fensterarbeiten | Fensteröffnung | 0 | 7.5 | NEW | 1205Wa 0000003986 | 0 | - | 0,51 | AllplanAttributes - ash D_Detailverweis: <undefiniert>; U-Wert: 0.9; Schallschutzklasse: 32; Sonnenschutztyp: Movable
Fensteröffnung | H2 Ebene +2 | 1205Fen2005825687 | m² | 0 | Fensterarbeiten | Fensteröffnung | 0 | 7.5 | NEW | 1205Wa 0000003986 | 0 | - | 0,51 | AllplanAttributes - ash D_Detailverweis: <undefiniert>; U-Wert: 0.9; Schallschutzklasse: 32; Sonnenschutztyp: Movable
Fensteröffnung | H2 Ebene +2 | 1205Fen2005825459 | m² | 0 | Fensterarbeiten | Fensteröffnung | 0 | 7.5 | NEW | 1205Wa 0000003986 | 0 | - | 0,51 | AllplanAttributes - ash D_Detailverweis: <undefiniert>; U-Wert: 0.9; Schallschutzklasse: 32; Sonnenschutztyp: Movable
Fensteröffnung | H2 Ebene +2 | 1205Fen2005825850 | m² | 0 | Fensterarbeiten | Fensteröffnung | 0 | 7.5 | NEW | 1205Wa 0000003996 | 0 | - | 0,51 | AllplanAttributes - ash D_Detailverweis: <undefiniert>; U-Wert: 0.9; Schallschutzklasse: 32; Sonnenschutztyp: Movable
Fensteröffnung | H2 Ebene +2 | 1205Fen2005825768 | m² | 0 | Fensterarbeiten | Fensteröffnung | 0 | 7.5 | NEW | 1205Wa 0000003996 | 0 | - | 0,51 | AllplanAttributes - ash D_Detailverweis: <undefiniert>; U-Wert: 0.9; Schallschutzklasse: 32; Sonnenschutztyp: Movable
Fensteröffnung | H2 Ebene +2 | 1205Fen2005825686 | m² | 0 | Fensterarbeiten | Fensteröffnung | 0 | 7.5 | NEW | 1205Wa 0000003996 | 0 | - | 0,51 | AllplanAttributes - ash D_Detailverweis: <undefiniert>; U-Wert: 0.9; Schallschutzklasse: 32; Sonnenschutztyp: Movable
Fensteröffnung | H2 Ebene +2 | 1205Fen2005825458 | m² | 0 | Fensterarbeiten | Fensteröffnung | 0 | 7.5 | NEW | 1205Wa 0000003996 | 0 | - | 0,51 | AllplanAttributes - ash D_Detailverweis: <undefiniert>; U-Wert: 0.9; Schallschutzklasse: 32; Sonnenschutztyp: Movable
Fensteröffnung | H2 Ebene +2 | 1205Fen2005825849 | m² | 0 | Fensterarbeiten | Fensteröffnung | 0 | 7.5 | NEW | 1205Wa 0000004006 | 0 | - | 0,51 | AllplanAttributes - ash D_Detailverweis: <undefiniert>; U-Wert: 0.9; Schallschutzklasse: 32; Sonnenschutztyp: Movable
Fensteröffnung | H2 Ebene +2 | 1205Fen2005825767 | m² | 0 | Fensterarbeiten | Fensteröffnung | 0 | 7.5 | NEW | 1205Wa 0000004006 | 0 | - | 0,51 | AllplanAttributes - ash D_Detailverweis: <undefiniert>; U-Wert: 0.9; Schallschutzklasse: 32; Sonnenschutztyp: Movable
Fensteröffnung | H2 Ebene +2 | 1205Fen2005825685 | m² | 0 | Fensterarbeiten | Fensteröffnung | 0 | 7.5 | NEW | 1205Wa 0000004006 | 0 | - | 0,51 | AllplanAttributes - ash D_Detailverweis: <undefiniert>; U-Wert: 0.9; Schallschutzklasse: 32; Sonnenschutztyp: Movable
Fensteröffnung | H2 Ebene +2 | 1205Fen2005825457 | m² | 0 | Fensterarbeiten | Fensteröffnung | 0 | 7.5 | NEW | 1205Wa 0000004006 | 0 | - | 0,51 | AllplanAttributes - ash D_Detailverweis: <undefiniert>; U-Wert: 0.9; Schallschutzklasse: 32; Sonnenschutztyp: Movable
Fensteröffnung | H2 Ebene +2 | 1205Fen2005825848 | m² | 0 | Fensterarbeiten | Fensteröffnung | 0 | 7.5 | NEW | 1105Wa 0811580073 | AllplanAttributes - Positionsnummer_Text: U23
Fensteröffnung | H2 Ebene +2 | 1205Fen2005825766 | m² | 0 | Fensterarbeiten | Fensteröffnung | 0 | 7.5 | NEW | 1105Wa 0811580073 | AllplanAttributes - Positionsnummer_Text: U23
Fensteröffnung | H2 Ebene +2 | 1205Fen2005825684 | m² | 0 | Fensterarbeiten | Fensteröffnung | 0 | 7.5 | NEW | 1105Wa 0811580073 | AllplanAttributes - Positionsnummer_Text: U23
Fensteröffnung | H2 Ebene +2 | 1205Fen2005825456 | m² | 0 | Fensterarbeiten | Fensteröffnung | 0 | 7.5 | NEW | 1105Wa 0811580073 | AllplanAttributes - Positionsnummer_Text: U23
Fensteröffnung | H2 Ebene +2 | 1205Fen2005827541 | m² | 0 | Fensterarbeiten | Fensteröffnung | 0 | 7.5 |  | 1205Wa 0000005300 | 0 | - | 0,51 | AllplanAttributes - ash D_Detailverweis: <undefiniert>; U-Wert: 0.9; Schallschutzklasse: 32; Sonnenschutztyp: Movable
Fensteröffnung | H2 Ebene +2 | 1205Fen2005827665 | m² | 0 | Fensterarbeiten | Fensteröffnung | 0 | 7.5 |  | 1205Wa 0000005300 | 0 | - | 0,51 | AllplanAttributes - ash D_Detailverweis: <undefiniert>; U-Wert: 0.9; Schallschutzklasse: 32; Sonnenschutztyp: Movable
Fensteröffnung | H2 Ebene +2 | 1205Fen2005827769 | m² | 0 | Fensterarbeiten | Fensteröffnung | 0 | 7.5 |  | 1205Wa 0000005300 | 0 | - | 0,51 | AllplanAttributes - ash D_Detailverweis: <undefiniert>; U-Wert: 0.9; Schallschutzklasse: 32; Sonnenschutztyp: Movable
Fensteröffnung | H2 Ebene +2 | 1205Fen2005827873 | m² | 0 | Fensterarbeiten | Fensteröffnung | 0 | 7.5 |  | 1205Wa 0000005300 | 0 | - | 0,51 | AllplanAttributes - ash D_Detailverweis: <undefiniert>; U-Wert: 0.9; Schallschutzklasse: 32; Sonnenschutztyp: Movable
Fensteröffnung | H2 Ebene +2 | 1205Fen2005827872 | m³ | 0 | Fensterarbeiten | Fensteröffnung | 0 | 7.5 |  | 1205Wa 0000005290 | 0 | - | 0,51 | AllplanAttributes - ash D_Detailverweis: <undefiniert>; U-Wert: 0.9; Schallschutzklasse: 32; Sonnenschutztyp: Movable
Fensteröffnung | H2 Ebene +2 | 1205Fen2005827540 | m³ | 0 | Fensterarbeiten | Fensteröffnung | 0 | 7.5 |  | 1205Wa 0000005290 | 0 | - | 0,51 | AllplanAttributes - ash D_Detailverweis: <undefiniert>; U-Wert: 0.9; Schallschutzklasse: 32; Sonnenschutztyp: Movable
Fensteröffnung | H2 Ebene +2 | 1205Fen2005827664 | m³ | 0 | Fensterarbeiten | Fensteröffnung | 0 | 7.5 |  | 1205Wa 0000005290 | 0 | - | 0,51 | AllplanAttributes - ash D_Detailverweis: <undefiniert>; U-Wert: 0.9; Schallschutzklasse: 32; Sonnenschutztyp: Movable
Fensteröffnung | H2 Ebene +2 | 1205Fen2005827768 | m³ | 0 | Fensterarbeiten | Fensteröffnung | 0 | 7.5 |  | 1205Wa 0000005290 | 0 | - | 0,51 | AllplanAttributes - ash D_Detailverweis: <undefiniert>; U-Wert: 0.9; Schallschutzklasse: 32; Sonnenschutztyp: Movable
Fensteröffnung | H2 Ebene +2 | 1205Fen2005827871 | m³ | 0 | Fensterarbeiten | Fensteröffnung | 0 | 7.5 |  | 1205Wa 0000005280 | 0 | - | 0,51 | AllplanAttributes - ash D_Detailverweis: <undefiniert>; U-Wert: 0.9; Schallschutzklasse: 32; Sonnenschutztyp: Movable
Fensteröffnung | H2 Ebene +2 | 1205Fen2005827539 | m³ | 0 | Fensterarbeiten | Fensteröffnung | 0 | 7.5 |  | 1205Wa 0000005280 | 0 | - | 0,51 | AllplanAttributes - ash D_Detailverweis: <undefiniert>; U-Wert: 0.9; Schallschutzklasse: 32; Sonnenschutztyp: Movable
Fensteröffnung | H2 Ebene +2 | 1205Fen2005827663 | m³ | 0 | Fensterarbeiten | Fensteröffnung | 0 | 7.5 |  | 1205Wa 0000005280 | 0 | - | 0,51 | AllplanAttributes - ash D_Detailverweis: <undefiniert>; U-Wert: 0.9; Schallschutzklasse: 32; Sonnenschutztyp: Movable
Fensteröffnung | H2 Ebene +2 | 1205Fen2005827767 | m³ | 0 | Fensterarbeiten | Fensteröffnung | 0 | 7.5 |  | 1205Wa 0000005280 | 0 | - | 0,51 | AllplanAttributes - ash D_Detailverweis: <undefiniert>; U-Wert: 0.9; Schallschutzklasse: 32; Sonnenschutztyp: Movable
Fensteröffnung | H2 Ebene +2 | 1205Fen2005827870 | m² | 0 | Fensterarbeiten | Fensteröffnung | 0 | 7.5 |  | 1205Wa 0000005270 | 0 | - | 0,51 | AllplanAttributes - ash D_Detailverweis: <undefiniert>; U-Wert: 0.9; Schallschutzklasse: 32; Sonnenschutztyp: Movable
Fensteröffnung | H2 Ebene +2 | 1205Fen2005827538 | m² | 0 | Fensterarbeiten | Fensteröffnung | 0 | 7.5 |  | 1205Wa 0000005270 | 0 | - | 0,51 | AllplanAttributes - ash D_Detailverweis: <undefiniert>; U-Wert: 0.9; Schallschutzklasse: 32; Sonnenschutztyp: Movable
Fensteröffnung | H2 Ebene +2 | 1205Fen2005827662 | m² | 0 | Fensterarbeiten | Fensteröffnung | 0 | 7.5 |  | 1205Wa 0000005270 | 0 | - | 0,51 | AllplanAttributes - ash D_Detailverweis: <undefiniert>; U-Wert: 0.9; Schallschutzklasse: 32; Sonnenschutztyp: Movable
Fensteröffnung | H2 Ebene +2 | 1205Fen2005827766 | m² | 0 | Fensterarbeiten | Fensteröffnung | 0 | 7.5 |  | 1205Wa 0000005270 | 0 | - | 0,51 | AllplanAttributes - ash D_Detailverweis: <undefiniert>; U-Wert: 0.9; Schallschutzklasse: 32; Sonnenschutztyp: Movable
Fensteröffnung | H2 Ebene +2 | 1205Fen2005827869 | m² | 0 | Fensterarbeiten | Fensteröffnung | 0 | 7.5 | NEW | 1205Wa 0000005260 | 0 | - | 0,51 | AllplanAttributes - ash D_Detailverweis: <undefiniert>; U-Wert: 0.9; Schallschutzklasse: 32; Sonnenschutztyp: Movable
Fensteröffnung | H2 Ebene +2 | 1205Fen2005827537 | m² | 0 | Fensterarbeiten | Fensteröffnung | 0 | 7.5 | NEW | 1205Wa 0000005260 | 0 | - | 0,51 | AllplanAttributes - ash D_Detailverweis: <undefiniert>; U-Wert: 0.9; Schallschutzklasse: 32; Sonnenschutztyp: Movable
Fensteröffnung | H2 Ebene +2 | 1205Fen2005827661 | m² | 0 | Fensterarbeiten | Fensteröffnung | 0 | 7.5 | NEW | 1205Wa 0000005260 | 0 | - | 0,51 | AllplanAttributes - ash D_Detailverweis: <undefiniert>; U-Wert: 0.9; Schallschutzklasse: 32; Sonnenschutztyp: Movable
Fensteröffnung | H2 Ebene +2 | 1205Fen2005827765 | m² | 0 | Fensterarbeiten | Fensteröffnung | 0 | 7.5 | NEW | 1205Wa 0000005260 | 0 | - | 0,51 | AllplanAttributes - ash D_Detailverweis: <undefiniert>; U-Wert: 0.9; Schallschutzklasse: 32; Sonnenschutztyp: Movable
Fensteröffnung | H2 Ebene +2 | 1205Fen2005827868 | m² | 0 | Fensterarbeiten | Fensteröffnung | 0 | 7.5 | NEW | 1205Wa 0000005250 | 0 | - | 0,51 | AllplanAttributes - ash D_Detailverweis: <undefiniert>; U-Wert: 0.9; Schallschutzklasse: 32; Sonnenschutztyp: Movable
Fensteröffnung | H2 Ebene +2 | 1205Fen2005827536 | m² | 0 | Fensterarbeiten | Fensteröffnung | 0 | 7.5 | NEW | 1205Wa 0000005250 | 0 | - | 0,51 | AllplanAttributes - ash D_Detailverweis: <undefiniert>; U-Wert: 0.9; Schallschutzklasse: 32; Sonnenschutztyp: Movable
Fensteröffnung | H2 Ebene +2 | 1205Fen2005827660 | m² | 0 | Fensterarbeiten | Fensteröffnung | 0 | 7.5 | NEW | 1205Wa 0000005250 | 0 | - | 0,51 | AllplanAttributes - ash D_Detailverweis: <undefiniert>; U-Wert: 0.9; Schallschutzklasse: 32; Sonnenschutztyp: Movable
Fensteröffnung | H2 Ebene +2 | 1205Fen2005827764 | m² | 0 | Fensterarbeiten | Fensteröffnung | 0 | 7.5 | NEW | 1205Wa 0000005250 | 0 | - | 0,51 | AllplanAttributes - ash D_Detailverweis: <undefiniert>; U-Wert: 0.9; Schallschutzklasse: 32; Sonnenschutztyp: Movable
Fensteröffnung | H2 Ebene +2 | 1205Fen2005827867 | m² | 0 | Fensterarbeiten | Fensteröffnung | 0 | 7.5 | NEW | 1205Wa 0000005240 | 0 | - | 0,51 | AllplanAttributes - ash D_Detailverweis: <undefiniert>; U-Wert: 0.9; Schallschutzklasse: 32; Sonnenschutztyp: Movable
Fensteröffnung | H2 Ebene +2 | 1205Fen2005827535 | m² | 0 | Fensterarbeiten | Fensteröffnung | 0 | 7.5 | NEW | 1205Wa 0000005240 | 0 | - | 0,51 | AllplanAttributes - ash D_Detailverweis: <undefiniert>; U-Wert: 0.9; Schallschutzklasse: 32; Sonnenschutztyp: Movable
Fensteröffnung | H2 Ebene +2 | 1205Fen2005827659 | m² | 0 | Fensterarbeiten | Fensteröffnung | 0 | 7.5 | NEW | 1205Wa 0000005240 | 0 | - | 0,51 | AllplanAttributes - ash D_Detailverweis: <undefiniert>; U-Wert: 0.9; Schallschutzklasse: 32; Sonnenschutztyp: Movable
Fensteröffnung | H2 Ebene +2 | 1205Fen2005827763 | m² | 0 | Fensterarbeiten | Fensteröffnung | 0 | 7.5 | NEW | 1205Wa 0000005240 | 0 | - | 0,51 | AllplanAttributes - ash D_Detailverweis: <undefiniert>; U-Wert: 0.9; Schallschutzklasse: 32; Sonnenschutztyp: Movable
Fensteröffnung | H2 Ebene +2 | 1205Fen2005859217 | m² | 0 | Fensterarbeiten | Fensteröffnung | 0 | 7.5 |  | 1205Wa 0000004893 | 0 | - | 0,51 | AllplanAttributes - ash D_Detailverweis: <undefiniert>; U-Wert: 0.9; Schallschutzklasse: 32; Sonnenschutztyp: Movable
Fensteröffnung | H2 Ebene +2 | 1205Fen2005859494 | m² | 0 | Fensterarbeiten | Fensteröffnung | 0 | 7.5 |  | 1205Wa 0000003947 | 0 | - | 0,51 | AllplanAttributes - ash D_Detailverweis: <undefiniert>; U-Wert: 0.9; Schallschutzklasse: 32; Sonnenschutztyp: Movable
Fensteröffnung | H2 Ebene +2 | 1205Fen2005859385 | m² | 0 | Fensterarbeiten | Fensteröffnung | 0 | 7.5 |  | 1205Wa 0000003947 | 0 | - | 0,51 | AllplanAttributes - ash D_Detailverweis: <undefiniert>; U-Wert: 0.9; Schallschutzklasse: 32; Sonnenschutztyp: Movable
Fensteröffnung | H2 Ebene +2 | 1205Fen2005859128 | m² | 0 | Fensterarbeiten | Fensteröffnung | 0 | 7.5 |  | 1205Wa 0000003947 | 0 | - | 0,51 | AllplanAttributes - ash D_Detailverweis: <undefiniert>; U-Wert: 0.9; Schallschutzklasse: 32; Sonnenschutztyp: Movable
Fensteröffnung | H2 Ebene +2 | 1205Fen2005859039 | m² | 0 | Fensterarbeiten | Fensteröffnung | 0 | 7.5 |  | 1205Wa 0000003947 | 0 | - | 0,51 | AllplanAttributes - ash D_Detailverweis: <undefiniert>; U-Wert: 0.9; Schallschutzklasse: 32; Sonnenschutztyp: Movable
Fensteröffnung | H2 Ebene +2 | 1205Fen2005859216 | m³ | 0 | Fensterarbeiten | Fensteröffnung | 0 | 7.5 |  | 1205Wa 0000004889 | 0 | - | 0,51 | AllplanAttributes - ash D_Detailverweis: <undefiniert>; U-Wert: 0.9; Schallschutzklasse: 32; Sonnenschutztyp: Movable
Fensteröffnung | H2 Ebene +2 | 1205Fen2005859493 | m³ | 0 | Fensterarbeiten | Fensteröffnung | 0 | 7.5 |  | 1205Wa 0000003957 | 0 | - | 0,51 | AllplanAttributes - ash D_Detailverweis: <undefiniert>; U-Wert: 0.9; Schallschutzklasse: 32; Sonnenschutztyp: Movable
Fensteröffnung | H2 Ebene +2 | 1205Fen2005859384 | m³ | 0 | Fensterarbeiten | Fensteröffnung | 0 | 7.5 |  | 1205Wa 0000003957 | 0 | - | 0,51 | AllplanAttributes - ash D_Detailverweis: <undefiniert>; U-Wert: 0.9; Schallschutzklasse: 32; Sonnenschutztyp: Movable
Fensteröffnung | H2 Ebene +2 | 1205Fen2005859127 | m³ | 0 | Fensterarbeiten | Fensteröffnung | 0 | 7.5 |  | 1205Wa 0000003957 | 0 | - | 0,51 | AllplanAttributes - ash D_Detailverweis: <undefiniert>; U-Wert: 0.9; Schallschutzklasse: 32; Sonnenschutztyp: Movable
Fensteröffnung | H2 Ebene +2 | 1205Fen2005859038 | m³ | 0 | Fensterarbeiten | Fensteröffnung | 0 | 7.5 |  | 1205Wa 0000003957 | 0 | - | 0,51 | AllplanAttributes - ash D_Detailverweis: <undefiniert>; U-Wert: 0.9; Schallschutzklasse: 32; Sonnenschutztyp: Movable
Fensteröffnung | H2 Ebene +2 | 1205Fen2005859215 | m³ | 0 | Fensterarbeiten | Fensteröffnung | 0 | 7.5 |  | 1205Wa 0000004885 | 0 | - | 0,51 | AllplanAttributes - ash D_Detailverweis: <undefiniert>; U-Wert: 0.9; Schallschutzklasse: 32; Sonnenschutztyp: Movable
Fensteröffnung | H2 Ebene +2 | 1205Fen2005859492 | m³ | 0 | Fensterarbeiten | Fensteröffnung | 0 | 7.5 |  | 1205Wa 0000003966 | 0 | - | 0,51 | AllplanAttributes - ash D_Detailverweis: <undefiniert>; U-Wert: 0.9; Schallschutzklasse: 32; Sonnenschutztyp: Movable
Fensteröffnung | H2 Ebene +2 | 1205Fen2005859383 | m³ | 0 | Fensterarbeiten | Fensteröffnung | 0 | 7.5 |  | 1205Wa 0000003966 | 0 | - | 0,51 | AllplanAttributes - ash D_Detailverweis: <undefiniert>; U-Wert: 0.9; Schallschutzklasse: 32; Sonnenschutztyp: Movable
Fensteröffnung | H2 Ebene +2 | 1205Fen2005859126 | m³ | 0 | Fensterarbeiten | Fensteröffnung | 0 | 7.5 |  | 1205Wa 0000003966 | 0 | - | 0,51 | AllplanAttributes - ash D_Detailverweis: <undefiniert>; U-Wert: 0.9; Schallschutzklasse: 32; Sonnenschutztyp: Movable
Fensteröffnung | H2 Ebene +2 | 1205Fen2005859037 | m³ | 0 | Fensterarbeiten | Fensteröffnung | 0 | 7.5 |  | 1205Wa 0000003966 | 0 | - | 0,51 | AllplanAttributes - ash D_Detailverweis: <undefiniert>; U-Wert: 0.9; Schallschutzklasse: 32; Sonnenschutztyp: Movable
Fensteröffnung | H2 Ebene +2 | 1205Fen2005859214 | m³ | 0 | Fensterarbeiten | Fensteröffnung | 0 | 7.5 |  | 1205Wa 0000004881 | 0 | - | 0,51 | AllplanAttributes - ash D_Detailverweis: <undefiniert>; U-Wert: 0.9; Schallschutzklasse: 32; Sonnenschutztyp: Movable
Fensteröffnung | H2 Ebene +2 | 1205Fen2005859491 | m³ | 0 | Fensterarbeiten | Fensteröffnung | 0 | 7.5 |  | 1205Wa 0000003976 | 0 | - | 0,51 | AllplanAttributes - ash D_Detailverweis: <undefiniert>; U-Wert: 0.9; Schallschutzklasse: 32; Sonnenschutztyp: Movable
Fensteröffnung | H2 Ebene +2 | 1205Fen2005859382 | m³ | 0 | Fensterarbeiten | Fensteröffnung | 0 | 7.5 |  | 1205Wa 0000003976 | 0 | - | 0,51 | AllplanAttributes - ash D_Detailverweis: <undefiniert>; U-Wert: 0.9; Schallschutzklasse: 32; Sonnenschutztyp: Movable
Fensteröffnung | H2 Ebene +2 | 1205Fen2005859125 | m³ | 0 | Fensterarbeiten | Fensteröffnung | 0 | 7.5 |  | 1205Wa 0000003976 | 0 | - | 0,51 | AllplanAttributes - ash D_Detailverweis: <undefiniert>; U-Wert: 0.9; Schallschutzklasse: 32; Sonnenschutztyp: Movable
Fensteröffnung | H2 Ebene +2 | 1205Fen2005859036 | m³ | 0 | Fensterarbeiten | Fensteröffnung | 0 | 7.5 |  | 1205Wa 0000003976 | 0 | - | 0,51 | AllplanAttributes - ash D_Detailverweis: <undefiniert>; U-Wert: 0.9; Schallschutzklasse: 32; Sonnenschutztyp: Movable
Fensteröffnung | H2 Ebene +2 | 1205Fen2005859213 | m² | 0 | Fensterarbeiten | Fensteröffnung | 0 | 7.5 | NEW | 1205Wa 0000004877 | 0 | - | 0,51 | AllplanAttributes - ash D_Detailverweis: <undefiniert>; U-Wert: 0.9; Schallschutzklasse: 32; Sonnenschutztyp: Movable
Fensteröffnung | H2 Ebene +2 | 1205Fen2005859490 | m² | 0 | Fensterarbeiten | Fensteröffnung | 0 | 7.5 | NEW | 1205Wa 0000003986 | 0 | - | 0,51 | AllplanAttributes - ash D_Detailverweis: <undefiniert>; U-Wert: 0.9; Schallschutzklasse: 32; Sonnenschutztyp: Movable
Fensteröffnung | H2 Ebene +2 | 1205Fen2005859381 | m² | 0 | Fensterarbeiten | Fensteröffnung | 0 | 7.5 | NEW | 1205Wa 0000003986 | 0 | - | 0,51 | AllplanAttributes - ash D_Detailverweis: <undefiniert>; U-Wert: 0.9; Schallschutzklasse: 32; Sonnenschutztyp: Movable
Fensteröffnung | H2 Ebene +2 | 1205Fen2005859124 | m² | 0 | Fensterarbeiten | Fensteröffnung | 0 | 7.5 | NEW | 1205Wa 0000003986 | 0 | - | 0,51 | AllplanAttributes - ash D_Detailverweis: <undefiniert>; U-Wert: 0.9; Schallschutzklasse: 32; Sonnenschutztyp: Movable
Fensteröffnung | H2 Ebene +2 | 1205Fen2005859035 | m² | 0 | Fensterarbeiten | Fensteröffnung | 0 | 7.5 | NEW | 1205Wa 0000003986 | 0 | - | 0,51 | AllplanAttributes - ash D_Detailverweis: <undefiniert>; U-Wert: 0.9; Schallschutzklasse: 32; Sonnenschutztyp: Movable
Fensteröffnung | H2 Ebene +2 | 1205Fen2005859212 | m² | 0 | Fensterarbeiten | Fensteröffnung | 0 | 7.5 | NEW | 1205Wa 0000004873 | 0 | - | 0,51 | AllplanAttributes - ash D_Detailverweis: <undefiniert>; U-Wert: 0.9; Schallschutzklasse: 32; Sonnenschutztyp: Movable
Fensteröffnung | H2 Ebene +2 | 1205Fen2005859489 | m² | 0 | Fensterarbeiten | Fensteröffnung | 0 | 7.5 | NEW | 1205Wa 0000003996 | 0 | - | 0,51 | AllplanAttributes - ash D_Detailverweis: <undefiniert>; U-Wert: 0.9; Schallschutzklasse: 32; Sonnenschutztyp: Movable
Fensteröffnung | H2 Ebene +2 | 1205Fen2005859380 | m² | 0 | Fensterarbeiten | Fensteröffnung | 0 | 7.5 | NEW | 1205Wa 0000003996 | 0 | - | 0,51 | AllplanAttributes - ash D_Detailverweis: <undefiniert>; U-Wert: 0.9; Schallschutzklasse: 32; Sonnenschutztyp: Movable
Fensteröffnung | H2 Ebene +2 | 1205Fen2005859123 | m² | 0 | Fensterarbeiten | Fensteröffnung | 0 | 7.5 | NEW | 1205Wa 0000003996 | 0 | - | 0,51 | AllplanAttributes - ash D_Detailverweis: <undefiniert>; U-Wert: 0.9; Schallschutzklasse: 32; Sonnenschutztyp: Movable
Fensteröffnung | H2 Ebene +2 | 1205Fen2005859034 | m² | 0 | Fensterarbeiten | Fensteröffnung | 0 | 7.5 | NEW | 1205Wa 0000003996 | 0 | - | 0,51 | AllplanAttributes - ash D_Detailverweis: <undefiniert>; U-Wert: 0.9; Schallschutzklasse: 32; Sonnenschutztyp: Movable
Fensteröffnung | H2 Ebene +2 | 1205Fen2005859211 | m² | 0 | Fensterarbeiten | Fensteröffnung | 0 | 7.5 | NEW | 1205Wa 0000004869 | 0 | - | 0,51 | AllplanAttributes - ash D_Detailverweis: FSLH2; ash D_Plannummer: D833; U-Wert: 0.9; Schallschutzklasse: 32; Sonnenschutztyp: Movable
Fensteröffnung | H2 Ebene +2 | 1205Fen2005859488 | m² | 0 | Fensterarbeiten | Fensteröffnung | 0 | 7.5 | NEW | 1205Wa 0000004006 | 0 | - | 0,51 | AllplanAttributes - ash D_Detailverweis: <undefiniert>; U-Wert: 0.9; Schallschutzklasse: 32; Sonnenschutztyp: Movable
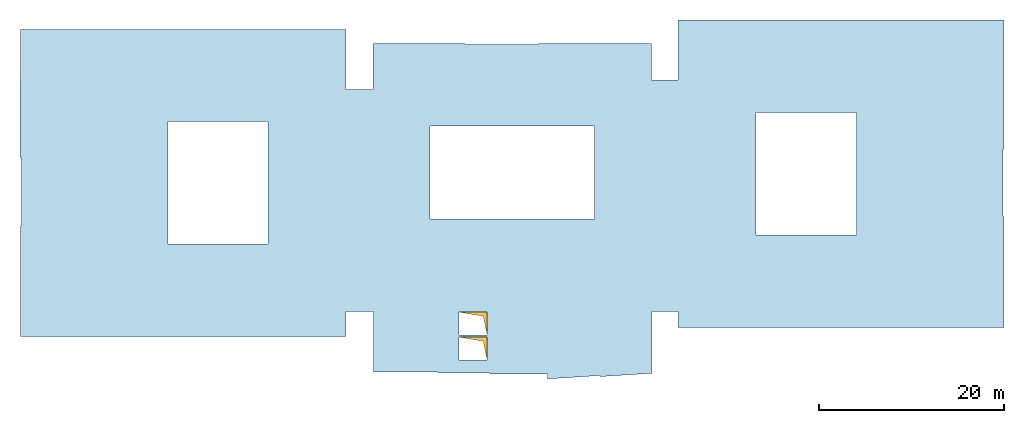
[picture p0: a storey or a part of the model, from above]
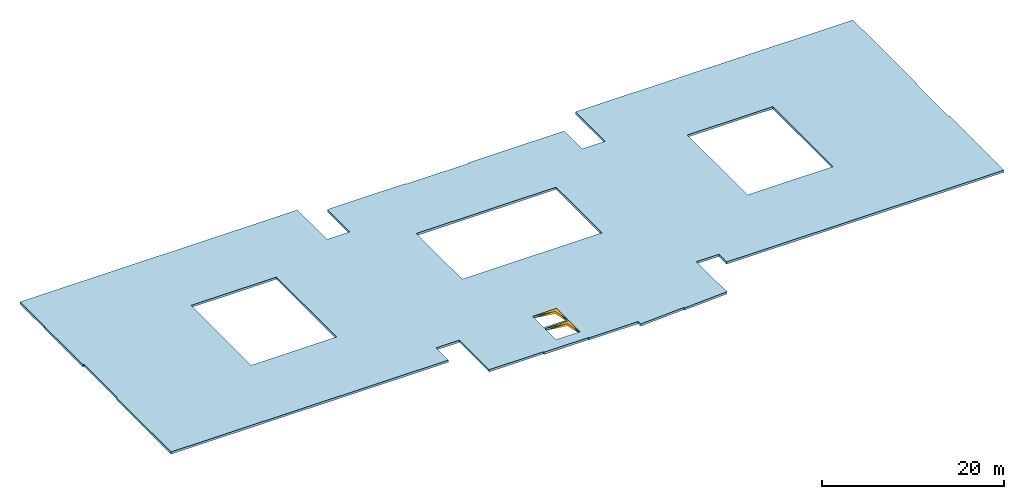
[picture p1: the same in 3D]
Properties of the parts of a building model (IFC4), part 33 of 80

# IfcOpeningElement: Opening (3497)
Name | In | Allright_Bauteil_ID | Abrechnungsart | Versatz_oben | Gewerk | Objektname | Versatz_unten | OKFF | Status | P_ID | AllplanAttributes, Feuerwiderstandsklasse | Sicherheitsklasse | g-Wert
Fensteröffnung | H2 Ebene +2 | 1205Fen2005859379 | m² | 0 | Fensterarbeiten | Fensteröffnung | 0 | 7.5 | NEW | 1205Wa 0000004006 | 0 | - | 0,51 | AllplanAttributes - ash D_Detailverweis: <undefiniert>; U-Wert: 0.9; Schallschutzklasse: 32; Sonnenschutztyp: Movable
Fensteröffnung | H2 Ebene +2 | 1205Fen2005859122 | m² | 0 | Fensterarbeiten | Fensteröffnung | 0 | 7.5 | NEW | 1205Wa 0000004006 | 0 | - | 0,51 | AllplanAttributes - ash D_Detailverweis: <undefiniert>; U-Wert: 0.9; Schallschutzklasse: 32; Sonnenschutztyp: Movable
Fensteröffnung | H2 Ebene +2 | 1205Fen2005859033 | m² | 0 | Fensterarbeiten | Fensteröffnung | 0 | 7.5 | NEW | 1205Wa 0000004006 | 0 | - | 0,51 | AllplanAttributes - ash D_Detailverweis: <undefiniert>; U-Wert: 0.9; Schallschutzklasse: 32; Sonnenschutztyp: Movable
Fensteröffnung | H2 Ebene +2 | 1205Fen2005859210 | m² | 0 | Fensterarbeiten | Fensteröffnung | 0 | 7.5 | NEW | 1105Wa 0811580073 | AllplanAttributes - Positionsnummer_Text: U23
Fensteröffnung | H2 Ebene +2 | 1205Fen2005859487 | m² | 0 | Fensterarbeiten | Fensteröffnung | 0 | 7.5 | NEW | 1105Wa 0811580073 | AllplanAttributes - Positionsnummer_Text: U23
Fensteröffnung | H2 Ebene +2 | 1205Fen2005859378 | m² | 0 | Fensterarbeiten | Fensteröffnung | 0 | 7.5 | NEW | 1105Wa 0811580073 | AllplanAttributes - Positionsnummer_Text: U23
Fensteröffnung | H2 Ebene +2 | 1205Fen2005859121 | m² | 0 | Fensterarbeiten | Fensteröffnung | 0 | 7.5 | NEW | 1105Wa 0811580073 | AllplanAttributes - Positionsnummer_Text: U23
Fensteröffnung | H2 Ebene +2 | 1205Fen2005859032 | m² | 0 | Fensterarbeiten | Fensteröffnung | 0 | 7.5 | NEW | 1105Wa 0811580073 | AllplanAttributes - Positionsnummer_Text: U23
Fensteröffnung | H2 Ebene +2 | 1205Fen0000279952 | m² |  | Wärmedämm-Verbundsysteme | Fensteröffnung |  | 7.5 | NEW | 1205Wa 0000178300 | 0 | - | 0,51 | AllplanAttributes - Material: Fensterelement; Tragendes Bauteil: no; Brandabschnittsdefinierendes Bauteil: no; ash D_Detailverweis: <undefiniert>; U-Wert: 0.9; Schallschutzklasse: 32; Sonnenschutztyp: Movable
Fensteröffnung | H2 Ebene +2 | 1205Fen0000279949 | m² |  | Wärmedämm-Verbundsysteme | Fensteröffnung |  | 7.5 | NEW | 1205Wa 0000178300 | 0 | - | 0,51 | AllplanAttributes - Material: Fensterelement; Tragendes Bauteil: no; Brandabschnittsdefinierendes Bauteil: no; ash D_Detailverweis: <undefiniert>; U-Wert: 0.9; Schallschutzklasse: 32; Sonnenschutztyp: Movable
Fensteröffnung | H2 Ebene +2 | 1205Fen0000279943 | m³ | 0 | Wärmedämm-Verbundsysteme | Fensteröffnung | 0 | 7.5 | NEW | 1205Wa 0000178299 | 0 | - | 0,51 | AllplanAttributes - Material: Fensterelement; Außenliegend: yes; ash D_Detailverweis: <undefiniert>; U-Wert: 0.9; Schallschutzklasse: 32; Sonnenschutztyp: Movable
Fensteröffnung | H2 Ebene +2 | 1205Fen0000279935 | m³ | 0 | Wärmedämm-Verbundsysteme | Fensteröffnung | 0 | 7.5 | NEW | 1205Wa 0000178299 | 0 | - | 0,51 | AllplanAttributes - Material: Fensterelement; Außenliegend: yes; ash D_Detailverweis: <undefiniert>; U-Wert: 0.9; Schallschutzklasse: 32; Sonnenschutztyp: Movable
Fensteröffnung | H2 Ebene +2 | 1205Fen0000279945 | m³ | 0 | Wärmedämm-Verbundsysteme | Fensteröffnung | 0 | 7.5 | NEW | 1205Wa 0000178298 | 0 | - | 0,51 | AllplanAttributes - ash D_Detailverweis: <undefiniert>; U-Wert: 0.9; Schallschutzklasse: 32; Sonnenschutztyp: Movable
Fensteröffnung | H2 Ebene +2 | 1205Fen0000279937 | m³ | 0 | Wärmedämm-Verbundsysteme | Fensteröffnung | 0 | 7.5 | NEW | 1205Wa 0000178298 | 0 | - | 0,51 | AllplanAttributes - ash D_Detailverweis: <undefiniert>; U-Wert: 0.9; Schallschutzklasse: 32; Sonnenschutztyp: Movable
Fensteröffnung | H2 Ebene +2 | 1205Fen0000279933 | m² | 0 | Wärmedämm-Verbundsysteme | Fensteröffnung | 0 | 7.5 | NEW | 1205Wa 0000178297 | 0 | - | 0,51 | AllplanAttributes - ash D_Detailverweis: <undefiniert>; U-Wert: 0.9; Schallschutzklasse: 32; Sonnenschutztyp: Movable
Fensteröffnung | H2 Ebene +2 | 1205Fen0000279925 | m² | 0 | Wärmedämm-Verbundsysteme | Fensteröffnung | 0 | 7.5 | NEW | 1205Wa 0000178297 | 0 | - | 0,51 | AllplanAttributes - ash D_Detailverweis: <undefiniert>; U-Wert: 0.9; Schallschutzklasse: 32; Sonnenschutztyp: Movable
Fensteröffnung | H2 Ebene +2 | 1205Fen0000279947 | m² | 0 | Wärmedämm-Verbundsysteme | Fensteröffnung | 0 | 7.5 | NEW | 1205Wa 0000178296 | 0 | - | 0,51 | AllplanAttributes - ash D_Detailverweis: <undefiniert>; U-Wert: 0.9; Schallschutzklasse: 32; Sonnenschutztyp: Movable
Fensteröffnung | H2 Ebene +2 | 1205Fen0000279931 | m² | 0 | Wärmedämm-Verbundsysteme | Fensteröffnung | 0 | 7.5 | NEW | 1205Wa 0000178296 | 0 | - | 0,51 | AllplanAttributes - ash D_Detailverweis: <undefiniert>; U-Wert: 0.9; Schallschutzklasse: 32; Sonnenschutztyp: Movable
Fensteröffnung | H2 Ebene +2 | 1205Fen0000279939 | m² | 0 | Wärmedämm-Verbundsysteme | Fensteröffnung | 0 | 7.5 | NEW | 1205Wa 0000178295 | 0 | - | 0,51 | AllplanAttributes - ash D_Detailverweis: <undefiniert>; U-Wert: 0.9; Schallschutzklasse: 32; Sonnenschutztyp: Movable
Fensteröffnung | H2 Ebene +2 | 1205Fen0000279929 | m² | 0 | Wärmedämm-Verbundsysteme | Fensteröffnung | 0 | 7.5 | NEW | 1205Wa 0000178295 | 0 | - | 0,51 | AllplanAttributes - ash D_Detailverweis: <undefiniert>; U-Wert: 0.9; Schallschutzklasse: 32; Sonnenschutztyp: Movable
Fensteröffnung | H2 Ebene +2 | 1205Fen0000279941 | m² | 0 | Wärmedämm-Verbundsysteme | Fensteröffnung | 0 | 7.5 | NEW | 1205Wa 0000178294 | 0 | - | 0,51 | AllplanAttributes - ash D_Detailverweis: <undefiniert>; U-Wert: 0.9; Schallschutzklasse: 32; Sonnenschutztyp: Movable
Fensteröffnung | H2 Ebene +2 | 1205Fen0000279927 | m² | 0 | Wärmedämm-Verbundsysteme | Fensteröffnung | 0 | 7.5 | NEW | 1205Wa 0000178294 | 0 | - | 0,51 | AllplanAttributes - ash D_Detailverweis: <undefiniert>; U-Wert: 0.9; Schallschutzklasse: 32; Sonnenschutztyp: Movable
Fensteröffnung | H2 Ebene +2 | 1205Fen0000279726 | m² |  | Wärmedämm-Verbundsysteme | Fensteröffnung |  | 7.5 | NEW | 1205Wa 0000176746 | 0 | - | 0,51 | AllplanAttributes - Material: Fensterelement; Tragendes Bauteil: no; Brandabschnittsdefinierendes Bauteil: no; ash D_Detailverweis: <undefiniert>; U-Wert: 0.9; Schallschutzklasse: 35; Sonnenschutztyp: Movable
Fensteröffnung | H2 Ebene +2 | 1205Fen0000279728 | m² |  | Wärmedämm-Verbundsysteme | Fensteröffnung |  | 7.5 | NEW | 1205Wa 0000176746 | 0 | - | 0,51 | AllplanAttributes - Material: Fensterelement; Tragendes Bauteil: no; Brandabschnittsdefinierendes Bauteil: no; ash D_Detailverweis: <undefiniert>; U-Wert: 0.9; Schallschutzklasse: 35; Sonnenschutztyp: Movable
Fensteröffnung | H2 Ebene +2 | 1205Fen0000279753 | m³ | 0 | Wärmedämm-Verbundsysteme | Fensteröffnung | 0 | 7.5 | NEW | 1205Wa 0000176745 | 0 | - | 0,51 | AllplanAttributes - Material: Fensterelement; Außenliegend: yes; ash D_Detailverweis: <undefiniert>; U-Wert: 0.9; Schallschutzklasse: 35; Sonnenschutztyp: Movable
Fensteröffnung | H2 Ebene +2 | 1205Fen0000279749 | m³ | 0 | Wärmedämm-Verbundsysteme | Fensteröffnung | 0 | 7.5 | NEW | 1205Wa 0000176745 | 0 | - | 0,51 | AllplanAttributes - Material: Fensterelement; Außenliegend: yes; ash D_Detailverweis: <undefiniert>; U-Wert: 0.9; Schallschutzklasse: 35; Sonnenschutztyp: Movable
Fensteröffnung | H2 Ebene +2 | 1205Fen0000279731 | m³ | 0 | Wärmedämm-Verbundsysteme | Fensteröffnung | 0 | 7.5 | NEW | 1205Wa 0000176744 | 0 | - | 0,51 | AllplanAttributes - ash D_Detailverweis: <undefiniert>; U-Wert: 0.9; Schallschutzklasse: 35; Sonnenschutztyp: Movable
Fensteröffnung | H2 Ebene +2 | 1205Fen0000279735 | m³ | 0 | Wärmedämm-Verbundsysteme | Fensteröffnung | 0 | 7.5 | NEW | 1205Wa 0000176744 | 0 | - | 0,51 | AllplanAttributes - ash D_Detailverweis: <undefiniert>; U-Wert: 0.9; Schallschutzklasse: 35; Sonnenschutztyp: Movable
Fensteröffnung | H2 Ebene +2 | 1205Fen0000279745 | m² | 0 | Wärmedämm-Verbundsysteme | Fensteröffnung | 0 | 7.5 | NEW | 1205Wa 0000176743 | 0 | - | 0,51 | AllplanAttributes - ash D_Detailverweis: <undefiniert>; U-Wert: 0.9; Schallschutzklasse: 35; Sonnenschutztyp: Movable
Fensteröffnung | H2 Ebene +2 | 1205Fen0000279751 | m² | 0 | Wärmedämm-Verbundsysteme | Fensteröffnung | 0 | 7.5 | NEW | 1205Wa 0000176743 | 0 | - | 0,51 | AllplanAttributes - ash D_Detailverweis: <undefiniert>; U-Wert: 0.9; Schallschutzklasse: 35; Sonnenschutztyp: Movable
Fensteröffnung | H2 Ebene +2 | 1205Fen0000279741 | m² | 0 | Wärmedämm-Verbundsysteme | Fensteröffnung | 0 | 7.5 | NEW | 1205Wa 0000176742 | 0 | - | 0,51 | AllplanAttributes - ash D_Detailverweis: <undefiniert>; U-Wert: 0.9; Schallschutzklasse: 35; Sonnenschutztyp: Movable
Fensteröffnung | H2 Ebene +2 | 1205Fen0000279739 | m² | 0 | Wärmedämm-Verbundsysteme | Fensteröffnung | 0 | 7.5 | NEW | 1205Wa 0000176742 | 0 | - | 0,51 | AllplanAttributes - ash D_Detailverweis: <undefiniert>; U-Wert: 0.9; Schallschutzklasse: 35; Sonnenschutztyp: Movable
Fensteröffnung | H2 Ebene +2 | 1205Fen0000279737 | m² | 0 | Wärmedämm-Verbundsysteme | Fensteröffnung | 0 | 7.5 | NEW | 1205Wa 0000176741 | 0 | - | 0,51 | AllplanAttributes - ash D_Detailverweis: <undefiniert>; U-Wert: 0.9; Schallschutzklasse: 35; Sonnenschutztyp: Movable
Fensteröffnung | H2 Ebene +2 | 1205Fen0000279733 | m² | 0 | Wärmedämm-Verbundsysteme | Fensteröffnung | 0 | 7.5 | NEW | 1205Wa 0000176741 | 0 | - | 0,51 | AllplanAttributes - ash D_Detailverweis: <undefiniert>; U-Wert: 0.9; Schallschutzklasse: 35; Sonnenschutztyp: Movable
Fensteröffnung | H2 Ebene +2 | 1205Fen0000279743 | m² | 0 | Wärmedämm-Verbundsysteme | Fensteröffnung | 0 | 7.5 | NEW | 1205Wa 0000176740 | 0 | - | 0,51 | AllplanAttributes - ash D_Detailverweis: <undefiniert>; U-Wert: 0.9; Schallschutzklasse: 35; Sonnenschutztyp: Movable
Fensteröffnung | H2 Ebene +2 | 1205Fen0000279747 | m² | 0 | Wärmedämm-Verbundsysteme | Fensteröffnung | 0 | 7.5 | NEW | 1205Wa 0000176740 | 0 | - | 0,51 | AllplanAttributes - ash D_Detailverweis: <undefiniert>; U-Wert: 0.9; Schallschutzklasse: 35; Sonnenschutztyp: Movable
Fensteröffnung | H2 Ebene +2 | 1205Fen0000280205 | m² |  | Wärmedämm-Verbundsysteme | Fensteröffnung |  | 7.5 | NEW | 1205Wa 0000002063 | 0 | - | 0,51 | AllplanAttributes - Material: Fensterelement; Tragendes Bauteil: no; Brandabschnittsdefinierendes Bauteil: no; ash D_Detailverweis: <undefiniert>; U-Wert: 0.9; Schallschutzklasse: 35; Sonnenschutztyp: Movable
Fensteröffnung | H2 Ebene +2 | 1205Fen0000281215 | m³ | 0 | Wärmedämm-Verbundsysteme | Fensteröffnung | 0 | 7.5 | NEW | 1205Wa 0000002059 | 0 | - | 0,51 | AllplanAttributes - Material: Fensterelement; Außenliegend: yes; ash D_Detailverweis: <undefiniert>; U-Wert: 0.9; Schallschutzklasse: 35; Sonnenschutztyp: Movable
Fensteröffnung | H2 Ebene +2 | 1205Fen0000280577 | m³ | 0 | Wärmedämm-Verbundsysteme | Fensteröffnung | 0 | 7.5 | NEW | 1205Wa 0000002055 | 0 | - | 0,51 | AllplanAttributes - ash D_Detailverweis: <undefiniert>; U-Wert: 0.9; Schallschutzklasse: 35; Sonnenschutztyp: Movable
Fensteröffnung | H2 Ebene +2 | 1205Fen0000281145 | m² | 0 | Wärmedämm-Verbundsysteme | Fensteröffnung | 0 | 7.5 | NEW | 1205Wa 0000002051 | 0 | - | 0,51 | AllplanAttributes - ash D_Detailverweis: <undefiniert>; U-Wert: 0.9; Schallschutzklasse: 35; Sonnenschutztyp: Movable
Fensteröffnung | H2 Ebene +2 | 1205Fen0000280615 | m² | 0 | Wärmedämm-Verbundsysteme | Fensteröffnung | 0 | 7.5 | NEW | 1205Wa 0000002047 | 0 | - | 0,51 | AllplanAttributes - ash D_Detailverweis: <undefiniert>; U-Wert: 0.9; Schallschutzklasse: 35; Sonnenschutztyp: Movable
Fensteröffnung | H2 Ebene +2 | 1205Fen0000280781 | m² | 0 | Wärmedämm-Verbundsysteme | Fensteröffnung | 0 | 7.5 | NEW | 1205Wa 0000002043 | 0 | - | 0,51 | AllplanAttributes - ash D_Detailverweis: <undefiniert>; U-Wert: 0.9; Schallschutzklasse: 35; Sonnenschutztyp: Movable
Fensteröffnung | H2 Ebene +2 | 1205Fen0000280679 | m² | 0 | Wärmedämm-Verbundsysteme | Fensteröffnung | 0 | 7.5 | NEW | 1205Wa 0000002039 | 0 | - | 0,51 | AllplanAttributes - ash D_Detailverweis: <undefiniert>; U-Wert: 0.9; Schallschutzklasse: 35; Sonnenschutztyp: Movable
Fensteröffnung | H2 Ebene +2 | 1205Fen0000280178 | m² |  | Wärmedämm-Verbundsysteme | Fensteröffnung |  | 7.5 | NEW | 1205Wa 0000000762 | 0 | - | 0,51 | AllplanAttributes - Material: Fensterelement; Tragendes Bauteil: no; Brandabschnittsdefinierendes Bauteil: no; ash D_Detailverweis: <undefiniert>; U-Wert: 0.9; Schallschutzklasse: 35; Sonnenschutztyp: Movable
Fensteröffnung | H2 Ebene +2 | 1205Fen0000280286 | m² |  | Wärmedämm-Verbundsysteme | Fensteröffnung |  | 7.5 | NEW | 1205Wa 0000000762 | 0 | - | 0,51 | AllplanAttributes - Material: Fensterelement; Tragendes Bauteil: no; Brandabschnittsdefinierendes Bauteil: no; ash D_Detailverweis: <undefiniert>; U-Wert: 0.9; Schallschutzklasse: 35; Sonnenschutztyp: Movable
Fensteröffnung | H2 Ebene +2 | 1205Fen0000281013 | m³ | 0 | Wärmedämm-Verbundsysteme | Fensteröffnung | 0 | 7.5 | NEW | 1205Wa 0000000758 | 0 | - | 0,51 | AllplanAttributes - Material: Fensterelement; Außenliegend: yes; ash D_Detailverweis: <undefiniert>; U-Wert: 0.9; Schallschutzklasse: 35; Sonnenschutztyp: Movable
Fensteröffnung | H2 Ebene +2 | 1205Fen0000281135 | m³ | 0 | Wärmedämm-Verbundsysteme | Fensteröffnung | 0 | 7.5 | NEW | 1205Wa 0000000758 | 0 | - | 0,51 | AllplanAttributes - Material: Fensterelement; Außenliegend: yes; ash D_Detailverweis: <undefiniert>; U-Wert: 0.9; Schallschutzklasse: 35; Sonnenschutztyp: Movable
Fensteröffnung | H2 Ebene +2 | 1205Fen0000280451 | m³ | 0 | Wärmedämm-Verbundsysteme | Fensteröffnung | 0 | 7.5 | NEW | 1205Wa 0000000738 | 0 | - | 0,51 | AllplanAttributes - ash D_Detailverweis: <undefiniert>; U-Wert: 0.9; Schallschutzklasse: 35; Sonnenschutztyp: Movable
Fensteröffnung | H2 Ebene +2 | 1205Fen0000280931 | m³ | 0 | Wärmedämm-Verbundsysteme | Fensteröffnung | 0 | 7.5 | NEW | 1205Wa 0000000738 | 0 | - | 0,51 | AllplanAttributes - ash D_Detailverweis: <undefiniert>; U-Wert: 0.9; Schallschutzklasse: 35; Sonnenschutztyp: Movable
Fensteröffnung | H2 Ebene +2 | 1205Fen0000280651 | m² | 0 | Wärmedämm-Verbundsysteme | Fensteröffnung | 0 | 7.5 | NEW | 1205Wa 0000000742 | 0 | - | 0,51 | AllplanAttributes - ash D_Detailverweis: <undefiniert>; U-Wert: 0.9; Schallschutzklasse: 35; Sonnenschutztyp: Movable
Fensteröffnung | H2 Ebene +2 | 1205Fen0000280801 | m² | 0 | Wärmedämm-Verbundsysteme | Fensteröffnung | 0 | 7.5 | NEW | 1205Wa 0000000742 | 0 | - | 0,51 | AllplanAttributes - ash D_Detailverweis: <undefiniert>; U-Wert: 0.9; Schallschutzklasse: 35; Sonnenschutztyp: Movable
Fensteröffnung | H2 Ebene +2 | 1205Fen0000281085 | m² | 0 | Wärmedämm-Verbundsysteme | Fensteröffnung | 0 | 7.5 | NEW | 1205Wa 0000000746 | 0 | - | 0,51 | AllplanAttributes - ash D_Detailverweis: <undefiniert>; U-Wert: 0.9; Schallschutzklasse: 35; Sonnenschutztyp: Movable
Fensteröffnung | H2 Ebene +2 | 1205Fen0000281037 | m² | 0 | Wärmedämm-Verbundsysteme | Fensteröffnung | 0 | 7.5 | NEW | 1205Wa 0000000746 | 0 | - | 0,51 | AllplanAttributes - ash D_Detailverweis: <undefiniert>; U-Wert: 0.9; Schallschutzklasse: 35; Sonnenschutztyp: Movable
Fensteröffnung | H2 Ebene +2 | 1205Fen0000280999 | m² | 0 | Wärmedämm-Verbundsysteme | Fensteröffnung | 0 | 7.5 | NEW | 1205Wa 0000000750 | 0 | - | 0,51 | AllplanAttributes - ash D_Detailverweis: <undefiniert>; U-Wert: 0.9; Schallschutzklasse: 35; Sonnenschutztyp: Movable
Fensteröffnung | H2 Ebene +2 | 1205Fen0000281077 | m² | 0 | Wärmedämm-Verbundsysteme | Fensteröffnung | 0 | 7.5 | NEW | 1205Wa 0000000750 | 0 | - | 0,51 | AllplanAttributes - ash D_Detailverweis: <undefiniert>; U-Wert: 0.9; Schallschutzklasse: 35; Sonnenschutztyp: Movable
Fensteröffnung | H2 Ebene +2 | 1205Fen0000281071 | m² | 0 | Wärmedämm-Verbundsysteme | Fensteröffnung | 0 | 7.5 | NEW | 1205Wa 0000000754 | 0 | - | 0,51 | AllplanAttributes - ash D_Detailverweis: <undefiniert>; U-Wert: 0.9; Schallschutzklasse: 35; Sonnenschutztyp: Movable
Fensteröffnung | H2 Ebene +2 | 1205Fen0000280725 | m² | 0 | Wärmedämm-Verbundsysteme | Fensteröffnung | 0 | 7.5 | NEW | 1205Wa 0000000754 | 0 | - | 0,51 | AllplanAttributes - ash D_Detailverweis: <undefiniert>; U-Wert: 0.9; Schallschutzklasse: 35; Sonnenschutztyp: Movable
Fensteröffnung | H2 Ebene +2 | 1205Fen0000280184 | m² |  | Wärmedämm-Verbundsysteme | Fensteröffnung |  | 7.5 | NEW | 1205Wa 0000000706 | 0 | - | 0,51 | AllplanAttributes - Material: Fensterelement; Tragendes Bauteil: no; Brandabschnittsdefinierendes Bauteil: no; ash D_Detailverweis: <undefiniert>; U-Wert: 0.9; Schallschutzklasse: 35; Sonnenschutztyp: Movable
Fensteröffnung | H2 Ebene +2 | 1205Fen0000280166 | m² |  | Wärmedämm-Verbundsysteme | Fensteröffnung |  | 7.5 | NEW | 1205Wa 0000000706 | 0 | - | 0,51 | AllplanAttributes - Material: Fensterelement; Tragendes Bauteil: no; Brandabschnittsdefinierendes Bauteil: no; ash D_Detailverweis: <undefiniert>; U-Wert: 0.9; Schallschutzklasse: 35; Sonnenschutztyp: Movable
Fensteröffnung | H2 Ebene +2 | 1205Fen0000281225 | m³ | 0 | Wärmedämm-Verbundsysteme | Fensteröffnung | 0 | 7.5 | NEW | 1205Wa 0000000710 | 0 | - | 0,51 | AllplanAttributes - Material: Fensterelement; Außenliegend: yes; ash D_Detailverweis: <undefiniert>; U-Wert: 0.9; Schallschutzklasse: 35; Sonnenschutztyp: Movable
Fensteröffnung | H2 Ebene +2 | 1205Fen0000280421 | m³ | 0 | Wärmedämm-Verbundsysteme | Fensteröffnung | 0 | 7.5 | NEW | 1205Wa 0000000710 | 0 | - | 0,51 | AllplanAttributes - Material: Fensterelement; Außenliegend: yes; ash D_Detailverweis: <undefiniert>; U-Wert: 0.9; Schallschutzklasse: 35; Sonnenschutztyp: Movable
Fensteröffnung | H2 Ebene +2 | 1205Fen0000281151 | m³ | 0 | Wärmedämm-Verbundsysteme | Fensteröffnung | 0 | 7.5 | NEW | 1205Wa 0000000730 | 0 | - | 0,51 | AllplanAttributes - ash D_Detailverweis: <undefiniert>; U-Wert: 0.9; Schallschutzklasse: 35; Sonnenschutztyp: Movable
Fensteröffnung | H2 Ebene +2 | 1205Fen0000280475 | m³ | 0 | Wärmedämm-Verbundsysteme | Fensteröffnung | 0 | 7.5 | NEW | 1205Wa 0000000730 | 0 | - | 0,51 | AllplanAttributes - ash D_Detailverweis: <undefiniert>; U-Wert: 0.9; Schallschutzklasse: 35; Sonnenschutztyp: Movable
Fensteröffnung | H2 Ebene +2 | 1205Fen0000280841 | m² | 0 | Wärmedämm-Verbundsysteme | Fensteröffnung | 0 | 7.5 | NEW | 1205Wa 0000000726 | 0 | - | 0,51 | AllplanAttributes - ash D_Detailverweis: <undefiniert>; U-Wert: 0.9; Schallschutzklasse: 35; Sonnenschutztyp: Movable
Fensteröffnung | H2 Ebene +2 | 1205Fen0000280629 | m² | 0 | Wärmedämm-Verbundsysteme | Fensteröffnung | 0 | 7.5 | NEW | 1205Wa 0000000726 | 0 | - | 0,51 | AllplanAttributes - ash D_Detailverweis: <undefiniert>; U-Wert: 0.9; Schallschutzklasse: 35; Sonnenschutztyp: Movable
Fensteröffnung | H2 Ebene +2 | 1205Fen0000280465 | m² | 0 | Wärmedämm-Verbundsysteme | Fensteröffnung | 0 | 7.5 | NEW | 1205Wa 0000000722 | 0 | - | 0,51 | AllplanAttributes - ash D_Detailverweis: <undefiniert>; U-Wert: 0.9; Schallschutzklasse: 35; Sonnenschutztyp: Movable
Fensteröffnung | H2 Ebene +2 | 1205Fen0000280793 | m² | 0 | Wärmedämm-Verbundsysteme | Fensteröffnung | 0 | 7.5 | NEW | 1205Wa 0000000722 | 0 | - | 0,51 | AllplanAttributes - ash D_Detailverweis: <undefiniert>; U-Wert: 0.9; Schallschutzklasse: 35; Sonnenschutztyp: Movable
Fensteröffnung | H2 Ebene +2 | 1205Fen0000280827 | m² | 0 | Wärmedämm-Verbundsysteme | Fensteröffnung | 0 | 7.5 | NEW | 1205Wa 0000000718 | 0 | - | 0,51 | AllplanAttributes - ash D_Detailverweis: <undefiniert>; U-Wert: 0.9; Schallschutzklasse: 35; Sonnenschutztyp: Movable
Fensteröffnung | H2 Ebene +2 | 1205Fen0000280707 | m² | 0 | Wärmedämm-Verbundsysteme | Fensteröffnung | 0 | 7.5 | NEW | 1205Wa 0000000718 | 0 | - | 0,51 | AllplanAttributes - ash D_Detailverweis: <undefiniert>; U-Wert: 0.9; Schallschutzklasse: 35; Sonnenschutztyp: Movable
Fensteröffnung | H2 Ebene +2 | 1205Fen0000280727 | m² | 0 | Wärmedämm-Verbundsysteme | Fensteröffnung | 0 | 7.5 | NEW | 1205Wa 0000000714 | 0 | - | 0,51 | AllplanAttributes - ash D_Detailverweis: <undefiniert>; U-Wert: 0.9; Schallschutzklasse: 35; Sonnenschutztyp: Movable
Fensteröffnung | H2 Ebene +2 | 1205Fen0000280479 | m² | 0 | Wärmedämm-Verbundsysteme | Fensteröffnung | 0 | 7.5 | NEW | 1205Wa 0000000714 | 0 | - | 0,51 | AllplanAttributes - ash D_Detailverweis: <undefiniert>; U-Wert: 0.9; Schallschutzklasse: 35; Sonnenschutztyp: Movable
Fensteröffnung | H2 Ebene +2 | 1205Fen0000280268 | m² |  | Wärmedämm-Verbundsysteme | Fensteröffnung |  | 7.5 | NEW | 1205Wa 0000002572 | 0 | - | 0,51 | AllplanAttributes - Material: Fensterelement; Tragendes Bauteil: no; Brandabschnittsdefinierendes Bauteil: no; ash D_Detailverweis: <undefiniert>; U-Wert: 0.9; Schallschutzklasse: 32; Sonnenschutztyp: Movable
Fensteröffnung | H2 Ebene +2 | 1205Fen0000281069 | m³ | 0 | Wärmedämm-Verbundsysteme | Fensteröffnung | 0 | 7.5 | NEW | 1205Wa 0000002576 | 0 | - | 0,51 | AllplanAttributes - Material: Fensterelement; Außenliegend: yes; ash D_Detailverweis: <undefiniert>; U-Wert: 0.9; Schallschutzklasse: 32; Sonnenschutztyp: Movable
Fensteröffnung | H2 Ebene +2 | 1205Fen0000280779 | m³ | 0 | Wärmedämm-Verbundsysteme | Fensteröffnung | 0 | 7.5 | NEW | 1205Wa 0000002580 | 0 | - | 0,51 | AllplanAttributes - ash D_Detailverweis: <undefiniert>; U-Wert: 0.9; Schallschutzklasse: 32; Sonnenschutztyp: Movable
Fensteröffnung | H2 Ebene +2 | 1205Fen0000280397 | m² | 0 | Wärmedämm-Verbundsysteme | Fensteröffnung | 0 | 7.5 | NEW | 1205Wa 0000002584 | 0 | - | 0,51 | AllplanAttributes - ash D_Detailverweis: <undefiniert>; U-Wert: 0.9; Schallschutzklasse: 32; Sonnenschutztyp: Movable
Fensteröffnung | H2 Ebene +2 | 1205Fen0000280593 | m² | 0 | Wärmedämm-Verbundsysteme | Fensteröffnung | 0 | 7.5 | NEW | 1205Wa 0000002588 | 0 | - | 0,51 | AllplanAttributes - ash D_Detailverweis: <undefiniert>; U-Wert: 0.9; Schallschutzklasse: 32; Sonnenschutztyp: Movable
Fensteröffnung | H2 Ebene +2 | 1205Fen0000280493 | m² | 0 | Wärmedämm-Verbundsysteme | Fensteröffnung | 0 | 7.5 | NEW | 1205Wa 0000002592 | 0 | - | 0,51 | AllplanAttributes - ash D_Detailverweis: <undefiniert>; U-Wert: 0.9; Schallschutzklasse: 32; Sonnenschutztyp: Movable
Fensteröffnung | H2 Ebene +2 | 1205Fen0000281105 | m² | 0 | Wärmedämm-Verbundsysteme | Fensteröffnung | 0 | 7.5 | NEW | 1205Wa 0000002596 | 0 | - | 0,51 | AllplanAttributes - ash D_Detailverweis: <undefiniert>; U-Wert: 0.9; Schallschutzklasse: 32; Sonnenschutztyp: Movable
Fensteröffnung | H2 Ebene +2 | 1205Fen0000280169 | m² |  | Wärmedämm-Verbundsysteme | Fensteröffnung |  | 7.5 | NEW | 1205Wa 0000000962 | 0 | - | 0,51 | AllplanAttributes - Material: Fensterelement; Tragendes Bauteil: no; Brandabschnittsdefinierendes Bauteil: no; ash D_Detailverweis: <undefiniert>; U-Wert: 0.9; Schallschutzklasse: 32; Sonnenschutztyp: Movable
Fensteröffnung | H2 Ebene +2 | 1205Fen0000280298 | m² |  | Wärmedämm-Verbundsysteme | Fensteröffnung |  | 7.5 | NEW | 1205Wa 0000000962 | 0 | - | 0,51 | AllplanAttributes - Material: Fensterelement; Tragendes Bauteil: no; Brandabschnittsdefinierendes Bauteil: no; ash D_Detailverweis: <undefiniert>; U-Wert: 0.9; Schallschutzklasse: 32; Sonnenschutztyp: Movable
Fensteröffnung | H2 Ebene +2 | 1205Fen0000280691 | m³ | 0 | Wärmedämm-Verbundsysteme | Fensteröffnung | 0 | 7.5 | NEW | 1205Wa 0000000958 | 0 | - | 0,51 | AllplanAttributes - Material: Fensterelement; Außenliegend: yes; ash D_Detailverweis: <undefiniert>; U-Wert: 0.9; Schallschutzklasse: 32; Sonnenschutztyp: Movable
Fensteröffnung | H2 Ebene +2 | 1205Fen0000281089 | m³ | 0 | Wärmedämm-Verbundsysteme | Fensteröffnung | 0 | 7.5 | NEW | 1205Wa 0000000958 | 0 | - | 0,51 | AllplanAttributes - Material: Fensterelement; Außenliegend: yes; ash D_Detailverweis: <undefiniert>; U-Wert: 0.9; Schallschutzklasse: 32; Sonnenschutztyp: Movable
Fensteröffnung | H2 Ebene +2 | 1205Fen0000280795 | m³ | 0 | Wärmedämm-Verbundsysteme | Fensteröffnung | 0 | 7.5 | NEW | 1205Wa 0000000938 | 0 | - | 0,51 | AllplanAttributes - ash D_Detailverweis: <undefiniert>; U-Wert: 0.9; Schallschutzklasse: 32; Sonnenschutztyp: Movable
Fensteröffnung | H2 Ebene +2 | 1205Fen0000280867 | m³ | 0 | Wärmedämm-Verbundsysteme | Fensteröffnung | 0 | 7.5 | NEW | 1205Wa 0000000938 | 0 | - | 0,51 | AllplanAttributes - ash D_Detailverweis: <undefiniert>; U-Wert: 0.9; Schallschutzklasse: 32; Sonnenschutztyp: Movable
Fensteröffnung | H2 Ebene +2 | 1205Fen0000281133 | m² | 0 | Wärmedämm-Verbundsysteme | Fensteröffnung | 0 | 7.5 | NEW | 1205Wa 0000000942 | 0 | - | 0,51 | AllplanAttributes - ash D_Detailverweis: <undefiniert>; U-Wert: 0.9; Schallschutzklasse: 32; Sonnenschutztyp: Movable
Fensteröffnung | H2 Ebene +2 | 1205Fen0000280699 | m² | 0 | Wärmedämm-Verbundsysteme | Fensteröffnung | 0 | 7.5 | NEW | 1205Wa 0000000942 | 0 | - | 0,51 | AllplanAttributes - ash D_Detailverweis: <undefiniert>; U-Wert: 0.9; Schallschutzklasse: 32; Sonnenschutztyp: Movable
Fensteröffnung | H2 Ebene +2 | 1205Fen0000281121 | m² | 0 | Wärmedämm-Verbundsysteme | Fensteröffnung | 0 | 7.5 | NEW | 1205Wa 0000000946 | 0 | - | 0,51 | AllplanAttributes - ash D_Detailverweis: <undefiniert>; U-Wert: 0.9; Schallschutzklasse: 32; Sonnenschutztyp: Movable
Fensteröffnung | H2 Ebene +2 | 1205Fen0000280715 | m² | 0 | Wärmedämm-Verbundsysteme | Fensteröffnung | 0 | 7.5 | NEW | 1205Wa 0000000946 | 0 | - | 0,51 | AllplanAttributes - ash D_Detailverweis: <undefiniert>; U-Wert: 0.9; Schallschutzklasse: 32; Sonnenschutztyp: Movable
Fensteröffnung | H2 Ebene +2 | 1205Fen0000281191 | m² | 0 | Wärmedämm-Verbundsysteme | Fensteröffnung | 0 | 7.5 | NEW | 1205Wa 0000000950 | 0 | - | 0,51 | AllplanAttributes - ash D_Detailverweis: <undefiniert>; U-Wert: 0.9; Schallschutzklasse: 32; Sonnenschutztyp: Movable
Fensteröffnung | H2 Ebene +2 | 1205Fen0000280989 | m² | 0 | Wärmedämm-Verbundsysteme | Fensteröffnung | 0 | 7.5 | NEW | 1205Wa 0000000950 | 0 | - | 0,51 | AllplanAttributes - ash D_Detailverweis: <undefiniert>; U-Wert: 0.9; Schallschutzklasse: 32; Sonnenschutztyp: Movable
Fensteröffnung | H2 Ebene +2 | 1205Fen0000280531 | m² | 0 | Wärmedämm-Verbundsysteme | Fensteröffnung | 0 | 7.5 | NEW | 1205Wa 0000000954 | 0 | - | 0,51 | AllplanAttributes - ash D_Detailverweis: <undefiniert>; U-Wert: 0.9; Schallschutzklasse: 32; Sonnenschutztyp: Movable
Fensteröffnung | H2 Ebene +2 | 1205Fen0000280815 | m² | 0 | Wärmedämm-Verbundsysteme | Fensteröffnung | 0 | 7.5 | NEW | 1205Wa 0000000954 | 0 | - | 0,51 | AllplanAttributes - ash D_Detailverweis: <undefiniert>; U-Wert: 0.9; Schallschutzklasse: 32; Sonnenschutztyp: Movable
Türöffnung | H2 Ebene +2 | 1213Tür0813004182 | m² |  | Trockenbauarbeiten | Türöffnung |  | 7.5 | NEW | 1213Wa 0812986179 | AllplanAttributes - Bezeichnung: Türöffnung; Codetext: Codetext; Türanschlag: -; Attributset-Objekt: OpeningElement; Ortscode_Geschoßbezeichnung: E02; Pset_OpeningElementCommon - FireExit: no; Reference: Codetext
Türöffnung | H2 Ebene +2 | 1213Tür0813004370 | m² |  | Trockenbauarbeiten | Türöffnung |  | 7.5 | NEW | 1213Wa 0812986264 | AllplanAttributes - Bezeichnung: Türöffnung; Codetext: Codetext; Türanschlag: -; Attributset-Objekt: OpeningElement; Ortscode_Geschoßbezeichnung: E02; Pset_OpeningElementCommon - FireExit: no; Reference: Codetext
Türöffnung | H2 Ebene +2 | 1213Tür0813004771 | m² |  | Trockenbauarbeiten | Türöffnung |  | 7.5 | NEW | 1213Wa 0812986176 | EI2 30 | AllplanAttributes - Codetext: Codetext; Türanschlag: -; Attributset-Objekt: OpeningElement; Rauchschutz: yes; Selbstschließend: yes; ash T_Zulage Schachttür: no; ash T_Dichtschließend: no; ash T_Feststellanlage (FSA): -; ash T_nicht abschließbar: no; Ortscode_Geschoßbezeichnung: E02; Pset_OpeningElementCommon - FireExit: no; Reference: Codetext
Türöffnung | H2 Ebene +2 | 1213Tür0813004783 | m² |  | Trockenbauarbeiten | Türöffnung |  | 7.5 | NEW | 1213Wa 0812985996 | EI2 30 | AllplanAttributes - Codetext: Codetext; Türanschlag: -; Attributset-Objekt: OpeningElement; Rauchschutz: yes; Selbstschließend: yes; ash T_Zulage Schachttür: no; ash T_Dichtschließend: no; ash T_Feststellanlage (FSA): -; ash T_nicht abschließbar: no; Ortscode_Geschoßbezeichnung: E02; Pset_OpeningElementCommon - FireExit: no; Reference: Codetext
Türöffnung | H2 Ebene +2 | 1213Tür0813004789 | m² |  | Trockenbauarbeiten | Türöffnung |  | 7.5 | NEW | 1213Wa 0812985996 | AllplanAttributes - Codetext: Codetext; Türanschlag: -; Attributset-Objekt: OpeningElement; Ortscode_Geschoßbezeichnung: E02; Pset_OpeningElementCommon - FireExit: no; Reference: Codetext
Türöffnung | H2 Ebene +2 | 1213Tür0813004759 | m² |  | Trockenbauarbeiten | Türöffnung |  | 7.5 | NEW | 1213Wa 0812986430 | AllplanAttributes - Codetext: Codetext; Türanschlag: DIN L; Attributset-Objekt: OpeningElement; Ortscode_Geschoßbezeichnung: E02; Pset_OpeningElementCommon - FireExit: no; Reference: Codetext
Türöffnung | H2 Ebene +2 | 1213Tür0813004753 | m² |  | Trockenbauarbeiten | Türöffnung |  | 7.5 | NEW | 1213Wa 0812986430 | AllplanAttributes - Codetext: Codetext; Türanschlag: DIN R; Attributset-Objekt: OpeningElement; Ortscode_Geschoßbezeichnung: E02; Pset_OpeningElementCommon - FireExit: no; Reference: Codetext
SMT | H2 Ebene +2 | 1213Tür0813004388 | m² |  | Zimmer- und Holzbauarbeiten | Türmakro |  | 7.5 | NEW | 1213Wa 0812986268 | AllplanAttributes - Material: TI-1F-UZ-D; Codetext: Codetext; Türanschlag: DIN L; Attributset-Objekt: Door; Glasanteil_berücksichtigen: 100; ash T_Zulage Schachttür: no; ash T_Dichtschließend: no; ash T_Zarge_Typ: U; ash T_Erforderl. Durchgangsbreite: 0 m; ash T_Türblatt sichtbar 2D: ja; ash T_Feststellanlage (FSA): -; ash T_nicht abschließbar: no; ash T_Tür-Nr.: Innentür 1; ash T_Blatt_Oberfläche: -; ash T_Erford. Durgangshöhe: 0 m; ash T_Blatt_Material: -; ash T_Schallschutz: -; ash T_Zarge_Material: S; ash T_Raum zugehörigkeit: BS; Ortscode_Geschoßbezeichnung: E02; Pset_OpeningElementCommon - FireExit: no; Reference: Codetext; DoorCommon - Außenliegend: no; Feuerwiderstandsklasse: EI2 30; Rauchschutz: yes; Selbstschließend: yes
Türöffnung | H2 Ebene +2 | 1213Tür0813004364 | m² |  | Trockenbauarbeiten | Türöffnung |  | 7.5 | NEW | 1213Wa 0812986261 | AllplanAttributes - Codetext: Codetext; Türanschlag: DIN R; Attributset-Objekt: OpeningElement; Ortscode_Geschoßbezeichnung: E02; Pset_OpeningElementCommon - FireExit: no; Reference: Codetext
Türöffnung | H2 Ebene +2 | 1213Tür0813004358 | m² |  | Trockenbauarbeiten | Türöffnung |  | 7.5 | NEW | 1213Wa 0812986261 | AllplanAttributes - Codetext: Codetext; Türanschlag: DIN L; Attributset-Objekt: OpeningElement; Ortscode_Geschoßbezeichnung: E02; Pset_OpeningElementCommon - FireExit: no; Reference: Codetext
Türöffnung | H2 Ebene +2 | 1213Tür0813004653 | m² |  | Trockenbauarbeiten | Türöffnung |  | 7.5 | NEW | 1213Wa 0812986333 | AllplanAttributes - Bezeichnung: Türöffnung; Codetext: Codetext; Türanschlag: -; Attributset-Objekt: OpeningElement; Ortscode_Geschoßbezeichnung: E02; Pset_OpeningElementCommon - FireExit: no; Reference: Codetext
Türöffnung | H2 Ebene +2 | 1213Tür0813004648 | m² |  | Trockenbauarbeiten | Türöffnung |  | 7.5 | NEW | 1213Wa 0812986329 | AllplanAttributes - Bezeichnung: Türöffnung; Codetext: Codetext; Türanschlag: -; Attributset-Objekt: OpeningElement; Ortscode_Geschoßbezeichnung: E02; Pset_OpeningElementCommon - FireExit: no; Reference: Codetext
Türöffnung | H2 Ebene +2 | 1213Tür0813004673 | m² |  | Trockenbauarbeiten | Türöffnung |  | 7.5 | NEW | 1213Wa 0812986325 | AllplanAttributes - Codetext: Codetext; Türanschlag: -; Attributset-Objekt: OpeningElement; Ortscode_Geschoßbezeichnung: E02; Pset_OpeningElementCommon - FireExit: no; Reference: Codetext
Türöffnung | H2 Ebene +2 | 1213Tür0813004658 | m² |  | Trockenbauarbeiten | Türöffnung |  | 7.5 | NEW | 1213Wa 0812986321 | AllplanAttributes - Bezeichnung: Türöffnung; Codetext: Codetext; Türanschlag: -; Attributset-Objekt: OpeningElement; Ortscode_Geschoßbezeichnung: E02; Pset_OpeningElementCommon - FireExit: no; Reference: Codetext
Türöffnung | H2 Ebene +2 | 1213Tür0813004663 | m² |  | Trockenbauarbeiten | Türöffnung |  | 7.5 | NEW | 1213Wa 0812986337 | AllplanAttributes - Bezeichnung: Türöffnung; Codetext: Codetext; Türanschlag: -; Attributset-Objekt: OpeningElement; Ortscode_Geschoßbezeichnung: E02; Pset_OpeningElementCommon - FireExit: no; Reference: Codetext
Türöffnung | H2 Ebene +2 | 1213Tür0813004668 | m² |  | Trockenbauarbeiten | Türöffnung |  | 7.5 | NEW | 1213Wa 0812986341 | AllplanAttributes - Bezeichnung: Türöffnung; Codetext: Codetext; Türanschlag: -; Attributset-Objekt: OpeningElement; Ortscode_Geschoßbezeichnung: E02; Pset_OpeningElementCommon - FireExit: no; Reference: Codetext
Türöffnung | H2 Ebene +2 | 1213Tür0813004466 | m² |  | Trockenbauarbeiten | Türöffnung |  | 7.5 | NEW | 1213Wa 0812986272 | AllplanAttributes - Codetext: Codetext; Türanschlag: -; Attributset-Objekt: OpeningElement; Ortscode_Geschoßbezeichnung: E02; Pset_OpeningElementCommon - FireExit: no; Reference: Codetext
Türöffnung | H2 Ebene +2 | 1213Tür0813004308 | m² |  | Trockenbauarbeiten | Türöffnung |  | 7.5 | NEW | 1213Wa 0812986222 | AllplanAttributes - Bezeichnung: Türöffnung; Codetext: Codetext; Türanschlag: -; Attributset-Objekt: OpeningElement; Ortscode_Geschoßbezeichnung: E02; Pset_OpeningElementCommon - FireExit: no; Reference: Codetext
Türöffnung | H2 Ebene +2 | 1213Tür0813004313 | m² |  | Trockenbauarbeiten | Türöffnung |  | 7.5 | NEW | 1213Wa 0812986226 | AllplanAttributes - Bezeichnung: Türöffnung; Codetext: Codetext; Türanschlag: -; Attributset-Objekt: OpeningElement; Ortscode_Geschoßbezeichnung: E02; Pset_OpeningElementCommon - FireExit: no; Reference: Codetext
Türöffnung | H2 Ebene +2 | 1213Tür0813004318 | m² |  | Trockenbauarbeiten | Türöffnung |  | 7.5 | NEW | 1213Wa 0812986103 | AllplanAttributes - Bezeichnung: Türöffnung; Codetext: Codetext; Türanschlag: -; Attributset-Objekt: OpeningElement; Ortscode_Geschoßbezeichnung: E02; Pset_OpeningElementCommon - FireExit: no; Reference: Codetext
Türöffnung | H2 Ebene +2 | 1213Tür0813004303 | m² |  | Trockenbauarbeiten | Türöffnung |  | 7.5 | NEW | 1213Wa 0812986214 | AllplanAttributes - Bezeichnung: Türöffnung; Codetext: Codetext; Türanschlag: -; Attributset-Objekt: OpeningElement; Ortscode_Geschoßbezeichnung: E02; Pset_OpeningElementCommon - FireExit: no; Reference: Codetext
Türöffnung | H2 Ebene +2 | 1213Tür0813004323 | m² |  | Trockenbauarbeiten | Türöffnung |  | 7.5 | NEW | 1213Wa 0812986218 | AllplanAttributes - Codetext: Codetext; Türanschlag: -; Attributset-Objekt: OpeningElement; Ortscode_Geschoßbezeichnung: E02; Pset_OpeningElementCommon - FireExit: no; Reference: Codetext
Türöffnung | H2 Ebene +2 | 1213Tür0813004298 | m² |  | Trockenbauarbeiten | Türöffnung |  | 7.5 | NEW | 1213Wa 0812986107 | AllplanAttributes - Bezeichnung: Türöffnung; Codetext: Codetext; Türanschlag: -; Attributset-Objekt: OpeningElement; Ortscode_Geschoßbezeichnung: E02; Pset_OpeningElementCommon - FireExit: no; Reference: Codetext
Türöffnung | H2 Ebene +2 | 1213Tür0813004193 | m² |  | Trockenbauarbeiten | Türöffnung |  | 7.5 | NEW | 1213Wa 0812986425 | AllplanAttributes - Bezeichnung: Türöffnung; Codetext: Codetext; Türanschlag: -; Attributset-Objekt: OpeningElement; Ortscode_Geschoßbezeichnung: E02; Pset_OpeningElementCommon - FireExit: no; Reference: Codetext
Türöffnung | H2 Ebene +2 | 1213Tür0813004188 | m² |  | Trockenbauarbeiten | Türöffnung |  | 7.5 | NEW | 1213Wa 0812986425 | AllplanAttributes - Bezeichnung: Türöffnung; Codetext: Codetext; Türanschlag: -; Attributset-Objekt: OpeningElement; Ortscode_Geschoßbezeichnung: E02; Pset_OpeningElementCommon - FireExit: no; Reference: Codetext
SMT | H2 Ebene +2 | 1213Tür0813004162 | m² |  | Metallbau-, Schlosserarbeiten | Türmakro |  | 7.5 | NEW | 1213Wa 0812986144 | AllplanAttributes - Material: TI-1F-UZ-D; Codetext: Codetext; Türanschlag: DIN R; Attributset-Objekt: Door; Positionsnummer: 1; V6: 0 m; V7: 0 m; V8: 0 m; V9: 0; Glasanteil_berücksichtigen: 100; ash T_Unterschnitt: -; ash T_Zulage Schachttür: no; ash T_Dichtschließend: yes; ash T_Zarge_Typ: U; ash T_Erforderl. Durchgangsbreite: 0 m; ash T_Türblatt sichtbar 2D: ja; ash T_Feststellanlage (FSA): -; ash T_nicht abschließbar: no; ash T_Blatt_Oberfläche: -; ash T_Erford. Durgangshöhe: 0 m; ash T_Blatt_Material: -; ash T_Schallschutz: -; ash T_Zarge_Material: S; ash T_Raum zugehörigkeit: BS; Ortscode_Geschoßbezeichnung: E02; Pset_OpeningElementCommon - FireExit: no; Reference: Codetext; DoorCommon - Außenliegend: no; Feuerwiderstandsklasse: -; Rauchschutz: no; Selbstschließend: no
Türöffnung | H2 Ebene +2 | 1213Tür0813057761 | m² |  | Trockenbauarbeiten | Türöffnung |  | 7.5 | NEW | 1213Wa 0813057764 | AllplanAttributes - Codetext: Codetext; Türanschlag: -; Attributset-Objekt: OpeningElement; Ortscode_Geschoßbezeichnung: E02; Pset_OpeningElementCommon - FireExit: no; Reference: Codetext
Türöffnung | H2 Ebene +2 | 1213Tür0813004678 | m² |  | Trockenbauarbeiten | Türöffnung |  | 7.5 | NEW | 1213Wa 0812986089 | EI2 30 | AllplanAttributes - Codetext: Codetext; Türanschlag: -; Attributset-Objekt: OpeningElement; Rauchschutz: yes; Selbstschließend: yes; ash T_Zulage Schachttür: no; ash T_Dichtschließend: no; ash T_Feststellanlage (FSA): -; ash T_nicht abschließbar: no; Ortscode_Geschoßbezeichnung: E02; Pset_OpeningElementCommon - FireExit: no; Reference: Codetext
Türöffnung | H2 Ebene +2 | 1213Tür0813004684 | m² |  | Trockenbauarbeiten | Türöffnung |  | 7.5 | NEW | 1213Wa 0812986089 | EI2 30 | AllplanAttributes - Codetext: Codetext; Türanschlag: -; Attributset-Objekt: OpeningElement; Rauchschutz: yes; Selbstschließend: yes; ash T_Zulage Schachttür: no; ash T_Dichtschließend: no; ash T_Feststellanlage (FSA): -; ash T_nicht abschließbar: no; Ortscode_Geschoßbezeichnung: E02; Pset_OpeningElementCommon - FireExit: no; Reference: Codetext
Türöffnung | H2 Ebene +2 | 1213Tür0813187682 | m² |  | Zimmer- und Holzbauarbeiten | Türöffnung |  | 7.5 | NEW | 1213Wa 0813187688 | AllplanAttributes - Türanschlag: -; Ortscode_Geschoßbezeichnung: E02
Türöffnung | H2 Ebene +2 | 1213Tür0813004170 | m² | 0 | Trockenbauarbeiten | Türöffnung | 0 | 7.5 | NEW | 1213Wa 0812986157 | AllplanAttributes - Codetext: Codetext; Türanschlag: -; Attributset-Objekt: OpeningElement; Ortscode_Geschoßbezeichnung: E02; Pset_OpeningElementCommon - FireExit: no; Reference: Codetext
SMT | H2 Ebene +2 | 1213Tür0813004720 | m² |  | Zimmer- und Holzbauarbeiten | Türmakro |  | 7.5 | NEW | 1213Wa 0812985936 | AllplanAttributes - Material: TI-1F-UZ-D; Codetext: Codetext; Türanschlag: DIN R; Attributset-Objekt: Door; Glasanteil_berücksichtigen: 100; ash T_Zulage Schachttür: no; ash T_Dichtschließend: no; ash T_Zarge_Typ: U; ash T_Erforderl. Durchgangsbreite: 0 m; ash T_Türblatt sichtbar 2D: ja; ash T_Feststellanlage (FSA): -; ash T_nicht abschließbar: no; ash T_Tür-Nr.: Innentür 1; ash T_Blatt_Oberfläche: -; ash T_Erford. Durgangshöhe: 0 m; ash T_Blatt_Material: -; ash T_Schallschutz: -; ash T_Zarge_Material: S; ash T_Raum zugehörigkeit: BS; Ortscode_Geschoßbezeichnung: E02; Pset_OpeningElementCommon - FireExit: no; Reference: Codetext; DoorCommon - Außenliegend: no; Feuerwiderstandsklasse: EI2 30; Rauchschutz: yes; Selbstschließend: yes
Türöffnung | H2 Ebene +2 | 1213Tür0813004150 | m² |  | Zimmer- und Holzbauarbeiten | Türöffnung |  | 7.5 | NEW | 1213Wa 0812986440 | AllplanAttributes - Codetext: Codetext; Türanschlag: DIN L; Attributset-Objekt: OpeningElement; Ortscode_Geschoßbezeichnung: E02; Pset_OpeningElementCommon - FireExit: no; Reference: Codetext
Türöffnung | H2 Ebene +2 | 1213Tür0813004097 | m² |  | Zimmer- und Holzbauarbeiten | Türöffnung |  | 7.5 | NEW | 1213Wa 0812986440 | EI2 30 | AllplanAttributes - Codetext: Codetext; Türanschlag: DIN L; Attributset-Objekt: OpeningElement; Rauchschutz: yes; Selbstschließend: yes; ash T_Zulage Schachttür: no; ash T_Dichtschließend: no; ash T_Feststellanlage (FSA): -; ash T_nicht abschließbar: no; Ortscode_Geschoßbezeichnung: E02; Pset_OpeningElementCommon - FireExit: no; Reference: Codetext
Wandnische | H2 Ebene +2 | 1213Wni0813568008 | m² | 0 | Zimmer- und Holzbauarbeiten | Wandnische | 0 | 7.5 | NEW | AllplanAttributes - Ortscode_Geschoßbezeichnung: E02
Türöffnung | H2 Ebene +2 | 1213Tür0813040100 | m² |  | Zimmer- und Holzbauarbeiten | Türöffnung |  | 7.5 | NEW | 1213Wa 0812985887 | E 60 | AllplanAttributes - Türanschlag: -; Text1: 15a; Ortscode_Geschoßbezeichnung: E02
Türöffnung | H2 Ebene +2 | 1213Tür0813005275 | m² |  | Zimmer- und Holzbauarbeiten | Türöffnung |  | 7.5 | NEW | 1213Wa 0812985887 | E 60 | AllplanAttributes - Türanschlag: -; Text1: 15a; Ortscode_Geschoßbezeichnung: E02
Fensteröffnung | H2 Ebene +2 | 1213Fen0812985805 | m² |  | Fensterarbeiten | Fensteröffnung |  | 7.5 |  | 1213Wa 0812985893 | AllplanAttributes - Ortscode_Geschoßbezeichnung: E02
Fensteröffnung | H2 Ebene +2 | 1213Fen0812985807 | m² |  | Fensterarbeiten | Fensteröffnung |  | 7.5 |  | 1213Wa 0812985893 | AllplanAttributes - Ortscode_Geschoßbezeichnung: E02
Türöffnung | H2 Ebene +2 | 1213Tür0813005461 | m² |  | Zimmer- und Holzbauarbeiten | Türöffnung |  | 7.5 | NEW | 1213Wa 0812985893 | REI 90-A1 | AllplanAttributes - Material: WA-STB; Tragendes Bauteil: yes; Brandabschnittsdefinierendes Bauteil: no; Außenliegend: yes; U-Wert: 0; Schallschutzklasse: 0; Codetext: Codetext; Türanschlag: -; Typ: 0; Brennbares Material: no; Brandverhalten: 0; Brandschutzklasse: A; Ortscode_Geschoßbezeichnung: E02; Pset_OpeningElementCommon - Reference: Codetext
Türöffnung | H2 Ebene +2 | 1213Tür0813004176 | m² | 0 | Trockenbauarbeiten | Türöffnung | 0 | 7.5 | NEW | 1213Wa 0812986161 | AllplanAttributes - Codetext: Codetext; Türanschlag: -; Attributset-Objekt: OpeningElement; Ortscode_Geschoßbezeichnung: E02; Pset_OpeningElementCommon - FireExit: no; Reference: Codetext
Türöffnung | H2 Ebene +2 | 1213Tür0813004595 | m² |  | Zimmer- und Holzbauarbeiten | Türöffnung |  | 7.5 | NEW | 1213Wa 0812986059 | AllplanAttributes - Codetext: Codetext; Türanschlag: DIN R; Attributset-Objekt: OpeningElement; Ortscode_Geschoßbezeichnung: E02; Pset_OpeningElementCommon - FireExit: no; Reference: Codetext
Türöffnung | H2 Ebene +2 | 1213Tür0813088796 | m² | 0 | Zimmer- und Holzbauarbeiten | Türöffnung | 0 | 7.5 | NEW | 1213Wa 0813088785 | AllplanAttributes - Türanschlag: DIN R; Ortscode_Geschoßbezeichnung: E02
Türöffnung | H2 Ebene +2 | 1213Tür0813004228 | m² |  | Trockenbauarbeiten | Türöffnung |  | 7.5 | NEW | 1213Wa 0812986450 | AllplanAttributes - Codetext: Codetext; Türanschlag: -; Attributset-Objekt: OpeningElement; Ortscode_Geschoßbezeichnung: E02; Pset_OpeningElementCommon - FireExit: no; Reference: Codetext
Fensteröffnung | H2 Ebene +2 | 1213Fen0813201087 | m² | 0 | Fensterarbeiten | Fensteröffnung | 0 | 7.5 |  | 1213Wa 0812971219 | AllplanAttributes - Ortscode_Geschoßbezeichnung: E02
Fensteröffnung | H2 Ebene +2 | 1213Fen0813200398 | m² |  | Fensterarbeiten | Fensteröffnung |  | 7.5 |  | 1213Wa 0812971219 | AllplanAttributes - Ortscode_Geschoßbezeichnung: E02
Türöffnung | H2 Ebene +2 | 1213Tür0813004213 | m² |  | Trockenbauarbeiten | Türöffnung |  | 7.5 | NEW | 1213Wa 0812986446 | AllplanAttributes - Codetext: Codetext; Türanschlag: -; Attributset-Objekt: OpeningElement; Ortscode_Geschoßbezeichnung: E02; Pset_OpeningElementCommon - FireExit: no; Reference: Codetext
Türöffnung | H2 Ebene +2 | 1213Tür0813004243 | m² |  | Zimmer- und Holzbauarbeiten | Türöffnung |  | 7.5 | NEW | 1213Wa 0812986072 | AllplanAttributes - Codetext: Codetext; Türanschlag: DIN L; Attributset-Objekt: OpeningElement; Ortscode_Geschoßbezeichnung: E02; Pset_OpeningElementCommon - FireExit: no; Reference: Codetext
Türöffnung | H2 Ebene +2 | 1213Tür0813083967 | m² | 0 | Zimmer- und Holzbauarbeiten | Türöffnung | 0 | 7.5 | NEW | 1213Wa 0813083945 | AllplanAttributes - Türanschlag: DIN L; Ortscode_Geschoßbezeichnung: E02
Türöffnung | H2 Ebene +2 | 1213Tür0813194284 | m² | 0 | Zimmer- und Holzbauarbeiten | Türöffnung | 0 | 7.5 | NEW | 1213Wa 0813194253 | AllplanAttributes - Türanschlag: DIN L; Ortscode_Geschoßbezeichnung: E02
Türöffnung | H2 Ebene +2 | 1213Tür0813004477 | m² |  | Zimmer- und Holzbauarbeiten | Türöffnung |  | 7.5 | NEW | 1213Wa 0812986135 | AllplanAttributes - Codetext: Codetext; Türanschlag: DIN R; Attributset-Objekt: OpeningElement; Ortscode_Geschoßbezeichnung: E02; Pset_OpeningElementCommon - FireExit: no; Reference: Codetext
Türöffnung | H2 Ebene +2 | 1213Tür0813084877 | m² | 0 | Zimmer- und Holzbauarbeiten | Türöffnung | 0 | 7.5 | NEW | 1213Wa 0813084864 | AllplanAttributes - Türanschlag: DIN R; Ortscode_Geschoßbezeichnung: E02
Türöffnung | H2 Ebene +2 | 1213Tür0813097177 | m² | 0 | Zimmer- und Holzbauarbeiten | Türöffnung | 0 | 7.5 | NEW | 1213Wa 0813097151 | AllplanAttributes - Türanschlag: DIN R; Ortscode_Geschoßbezeichnung: E02
Türöffnung | H2 Ebene +2 | 1213Tür0813004749 | m² |  | Zimmer- und Holzbauarbeiten | Türöffnung |  | 7.5 | NEW | 1213Wa 0812986357 | AllplanAttributes - Codetext: Codetext; Türanschlag: DIN L; Attributset-Objekt: OpeningElement; Ortscode_Geschoßbezeichnung: E02; Pset_OpeningElementCommon - FireExit: no; Reference: Codetext
Türöffnung | H2 Ebene +2 | 1213Tür0813088444 | m² | 0 | Zimmer- und Holzbauarbeiten | Türöffnung | 0 | 7.5 | NEW | 1213Wa 0813088433 | AllplanAttributes - Türanschlag: DIN L; Ortscode_Geschoßbezeichnung: E02
Türöffnung | H2 Ebene +2 | 1213Tür0813098369 | m² | 0 | Zimmer- und Holzbauarbeiten | Türöffnung | 0 | 7.5 | NEW | 1213Wa 0813098330 | AllplanAttributes - Türanschlag: DIN L; Ortscode_Geschoßbezeichnung: E02
Türöffnung | H2 Ebene +2 | 1213Tür0813004744 | m² |  | Zimmer- und Holzbauarbeiten | Türöffnung |  | 7.5 | NEW | 1213Wa 0812986353 | AllplanAttributes - Codetext: Codetext; Türanschlag: DIN L; Attributset-Objekt: OpeningElement; Ortscode_Geschoßbezeichnung: E02; Pset_OpeningElementCommon - FireExit: no; Reference: Codetext
Türöffnung | H2 Ebene +2 | 1213Tür0813088025 | m² | 0 | Zimmer- und Holzbauarbeiten | Türöffnung | 0 | 7.5 | NEW | 1213Wa 0813088012 | AllplanAttributes - Türanschlag: DIN L; Ortscode_Geschoßbezeichnung: E02
Türöffnung | H2 Ebene +2 | 1213Tür0813099650 | m² | 0 | Zimmer- und Holzbauarbeiten | Türöffnung | 0 | 7.5 | NEW | 1213Wa 0813099623 | AllplanAttributes - Türanschlag: DIN L; Ortscode_Geschoßbezeichnung: E02
Türöffnung | H2 Ebene +2 | 1213Tür0813004087 | m² |  | Zimmer- und Holzbauarbeiten | Türöffnung |  | 7.5 | NEW | 1213Wa 0812985917 | AllplanAttributes - Codetext: Codetext; Türanschlag: DIN R; Attributset-Objekt: OpeningElement; Ortscode_Geschoßbezeichnung: E02; Pset_OpeningElementCommon - FireExit: no; Reference: Codetext
Türöffnung | H2 Ebene +2 | 1213Tür0813087555 | m² | 0 | Zimmer- und Holzbauarbeiten | Türöffnung | 0 | 7.5 | NEW | 1213Wa 0813087544 | AllplanAttributes - Türanschlag: -; Ortscode_Geschoßbezeichnung: E02
Wandnische | H2 Ebene +2 | 1213Wni0813733057 | m² | 0 | Zimmer- und Holzbauarbeiten | Wandnische | 0 |  | NEW
Wandnische | H2 Ebene +2 | 1213Wni0813568000 | m² | 0 | Zimmer- und Holzbauarbeiten | Wandnische | 0 | 7.5 | NEW | AllplanAttributes - Ortscode_Geschoßbezeichnung: E02
Türöffnung | H2 Ebene +2 | 1213Tür0813004211 | m² |  | Trockenbauarbeiten | Türöffnung |  | 7.5 | NEW | 1213Wa 0812986443 | AllplanAttributes - Codetext: Codetext; Türanschlag: -; Attributset-Objekt: OpeningElement; Ortscode_Geschoßbezeichnung: E02; Pset_OpeningElementCommon - FireExit: no; Reference: Codetext
Türöffnung | H2 Ebene +2 | 1213Tür0813004765 | m² |  | Zimmer- und Holzbauarbeiten | Türöffnung |  | 7.5 | NEW | 1213Wa 0812986361 | AllplanAttributes - Codetext: Codetext; Türanschlag: DIN L; Attributset-Objekt: OpeningElement; Ortscode_Geschoßbezeichnung: E02; Pset_OpeningElementCommon - FireExit: no; Reference: Codetext
Fensteröffnung | H2 Ebene +2 | 1213Fen0813507834 | m² |  | Fensterarbeiten | Fensteröffnung |  | 7.5 |  | 1113Wa 0812437264 | AllplanAttributes - ash D_Detailverweis: D1833; Positionsnummer_Text: S68
Türöffnung | H2 Ebene +2 | 1213Tür0813004451 | m² |  | Trockenbauarbeiten | Türöffnung |  | 7.5 | NEW | 1213Wa 0812986111 | AllplanAttributes - Bezeichnung: Türöffnung; Codetext: Codetext; Türanschlag: -; Attributset-Objekt: OpeningElement; Ortscode_Geschoßbezeichnung: E02; Pset_OpeningElementCommon - FireExit: no; Reference: Codetext
Türöffnung | H2 Ebene +2 | 1213Tür0813004456 | m² |  | Trockenbauarbeiten | Türöffnung |  | 7.5 | NEW | 1213Wa 0812986256 | AllplanAttributes - Bezeichnung: Türöffnung; Codetext: Codetext; Türanschlag: -; Attributset-Objekt: OpeningElement; Ortscode_Geschoßbezeichnung: E02; Pset_OpeningElementCommon - FireExit: no; Reference: Codetext
Türöffnung | H2 Ebene +2 | 1213Tür0813004436 | m² |  | Trockenbauarbeiten | Türöffnung |  | 7.5 | NEW | 1213Wa 0812986244 | AllplanAttributes - Bezeichnung: Türöffnung; Codetext: Codetext; Türanschlag: -; Attributset-Objekt: OpeningElement; Ortscode_Geschoßbezeichnung: E02; Pset_OpeningElementCommon - FireExit: no; Reference: Codetext
Türöffnung | H2 Ebene +2 | 1213Tür0813004446 | m² |  | Trockenbauarbeiten | Türöffnung |  | 7.5 | NEW | 1213Wa 0812986252 | AllplanAttributes - Bezeichnung: Türöffnung; Codetext: Codetext; Türanschlag: -; Attributset-Objekt: OpeningElement; Ortscode_Geschoßbezeichnung: E02; Pset_OpeningElementCommon - FireExit: no; Reference: Codetext
Türöffnung | H2 Ebene +2 | 1213Tür0813004461 | m² |  | Trockenbauarbeiten | Türöffnung |  | 7.5 | NEW | 1213Wa 0812986248 | AllplanAttributes - Codetext: Codetext; Türanschlag: -; Attributset-Objekt: OpeningElement; Ortscode_Geschoßbezeichnung: E02; Pset_OpeningElementCommon - FireExit: no; Reference: Codetext
Türöffnung | H2 Ebene +2 | 1213Tür0813004441 | m² |  | Trockenbauarbeiten | Türöffnung |  | 7.5 | NEW | 1213Wa 0812986240 | AllplanAttributes - Bezeichnung: Türöffnung; Codetext: Codetext; Türanschlag: -; Attributset-Objekt: OpeningElement; Ortscode_Geschoßbezeichnung: E02; Pset_OpeningElementCommon - FireExit: no; Reference: Codetext
Türöffnung | H2 Ebene +2 | 1213Tür0813004498 | m² | 0 | Trockenbauarbeiten | Türöffnung | 0 | 7.5 | NEW | 1213Wa 0812986152 | AllplanAttributes - Codetext: Codetext; Türanschlag: -; Attributset-Objekt: OpeningElement; Ortscode_Geschoßbezeichnung: E02; Pset_OpeningElementCommon - FireExit: no; Reference: Codetext
Türöffnung | H2 Ebene +2 |  |  |  |  |  |  |  | NEW | Pset_OpeningElementCommon - FireExit: no; Reference: Codetext; AllplanAttributes - Object Layer Attributes #1, Gewerk: Trockenbauarbeiten; Object Layer Attributes #1, Allright_Bauteil_ID: 1213Tür0813004643; Object Layer Attributes #1, Abrechnungsart: m²; Object Layer Attributes #1, Objektname: Türöffnung; Object Layer Attributes #1, Codetext: Codetext; Object Layer Attributes #1, Ortscode_Geschoßbezeichnung: E02; Object Layer Attributes #1, Türanschlag: -; Object Layer Attributes #1, Bezeichnung: Türöffnung; Object Layer Attributes #1, OKFF: 7.5; Object Layer Attributes #1, Attributset-Objekt: OpeningElement; Object Layer Attributes #1, P_ID: 1213Wa 0812986465
Türöffnung | H2 Ebene +2 | 1213Tür0813563066 | m² |  | Trockenbauarbeiten | Türöffnung |  | 7.5 | NEW | 1213Wa 0812986345 | AllplanAttributes - Bezeichnung: Türöffnung; Codetext: Codetext; Türanschlag: -; Attributset-Objekt: OpeningElement; Ortscode_Geschoßbezeichnung: E02; Pset_OpeningElementCommon - FireExit: no; Reference: Codetext
Türöffnung | H2 Ebene +2 | 1213Tür0813004777 | m² |  | Trockenbauarbeiten | Türöffnung |  | 7.5 | NEW | 1213Wa 0812986349 | AllplanAttributes - Codetext: Codetext; Türanschlag: -; Attributset-Objekt: OpeningElement; Ortscode_Geschoßbezeichnung: E02; Pset_OpeningElementCommon - FireExit: no; Reference: Codetext
Türöffnung | H2 Ebene +2 | 1213Tür0813004328 | m² |  | Trockenbauarbeiten | Türöffnung |  | 7.5 | NEW | 1213Wa 0812986093 | AllplanAttributes - Bezeichnung: Türöffnung; Codetext: Codetext; Türanschlag: -; Attributset-Objekt: OpeningElement; Ortscode_Geschoßbezeichnung: E02; Pset_OpeningElementCommon - FireExit: no; Reference: Codetext
Türöffnung | H2 Ebene +2 | 1213Tür0813480838 | m² | 0 | Zimmer- und Holzbauarbeiten | Türöffnung | 0 | 7.5 | NEW | 1113Wa 0812444155 | AllplanAttributes - Türanschlag: DIN L; Positionsnummer_Text: S68; Ortscode_Geschoßbezeichnung: E02
Türöffnung | H2 Ebene +2 | 1213Tür0813480837 | m² | 0 | Zimmer- und Holzbauarbeiten | Türöffnung | 0 | 7.5 | NEW | AllplanAttributes - Türanschlag: DIN L; Ortscode_Geschoßbezeichnung: E02
Türöffnung | H2 Ebene +2 | 1213Tür0813480836 | m² | -30 | Zimmer- und Holzbauarbeiten | Türöffnung | 0 | 7.5 | NEW | AllplanAttributes - Türanschlag: DIN L; Ortscode_Geschoßbezeichnung: E02
Türöffnung | H2 Ebene +2 | 1213Tür0813004112 | m² |  | Zimmer- und Holzbauarbeiten | Türöffnung |  | 7.5 | NEW | 1213Wa 0812986438 | AllplanAttributes - Türanschlag: DIN L; Ortscode_Geschoßbezeichnung: E02
Türöffnung | H2 Ebene +2 | 1213Tür0813004110 | m² | 0 | Zimmer- und Holzbauarbeiten | Türöffnung | 0 | 7.5 | NEW | 1213Wa 0812985921 | AllplanAttributes - Türanschlag: DIN L; Ortscode_Geschoßbezeichnung: E02
Türöffnung | H2 Ebene +2 | 1213Tür0813004533 | m² |  | Trockenbauarbeiten | Türöffnung |  | 7.5 | NEW | 1213Wa 0812986317 | AllplanAttributes - Bezeichnung: Türöffnung; Codetext: Codetext; Türanschlag: -; Attributset-Objekt: OpeningElement; Ortscode_Geschoßbezeichnung: E02; Pset_OpeningElementCommon - FireExit: no; Reference: Codetext
Türöffnung | H2 Ebene +2 | 1213Tür0813004538 | m² |  | Trockenbauarbeiten | Türöffnung |  | 7.5 | NEW | 1213Wa 0812986313 | AllplanAttributes - Bezeichnung: Türöffnung; Codetext: Codetext; Türanschlag: -; Attributset-Objekt: OpeningElement; Ortscode_Geschoßbezeichnung: E02; Pset_OpeningElementCommon - FireExit: no; Reference: Codetext
Türöffnung | H2 Ebene +2 | 1213Tür0813004543 | m² |  | Trockenbauarbeiten | Türöffnung |  | 7.5 | NEW | 1213Wa 0812986305 | AllplanAttributes - Codetext: Codetext; Türanschlag: -; Attributset-Objekt: OpeningElement; Ortscode_Geschoßbezeichnung: E02; Pset_OpeningElementCommon - FireExit: no; Reference: Codetext
Türöffnung | H2 Ebene +2 | 1213Tür0813004528 | m² |  | Trockenbauarbeiten | Türöffnung |  | 7.5 | NEW | 1213Wa 0812986309 | AllplanAttributes - Bezeichnung: Türöffnung; Codetext: Codetext; Türanschlag: -; Attributset-Objekt: OpeningElement; Ortscode_Geschoßbezeichnung: E02; Pset_OpeningElementCommon - FireExit: no; Reference: Codetext
Türöffnung | H2 Ebene +2 | 1213Tür0813004523 | m² |  | Trockenbauarbeiten | Türöffnung |  | 7.5 | NEW | 1213Wa 0812986297 | AllplanAttributes - Bezeichnung: Türöffnung; Codetext: Codetext; Türanschlag: -; Attributset-Objekt: OpeningElement; Ortscode_Geschoßbezeichnung: E02; Pset_OpeningElementCommon - FireExit: no; Reference: Codetext
Türöffnung | H2 Ebene +2 | 1213Tür0813004518 | m² |  | Trockenbauarbeiten | Türöffnung |  | 7.5 | NEW | 1213Wa 0812986301 | AllplanAttributes - Bezeichnung: Türöffnung; Codetext: Codetext; Türanschlag: -; Attributset-Objekt: OpeningElement; Ortscode_Geschoßbezeichnung: E02; Pset_OpeningElementCommon - FireExit: no; Reference: Codetext
Türöffnung | H2 Ebene +2 | 1213Tür0813004548 | m² |  | Trockenbauarbeiten | Türöffnung |  | 7.5 | NEW | 1213Wa 0812986293 | AllplanAttributes - Codetext: Codetext; Türanschlag: -; Attributset-Objekt: OpeningElement; Ortscode_Geschoßbezeichnung: E02; Pset_OpeningElementCommon - FireExit: no; Reference: Codetext
Türöffnung | H2 Ebene +2 | 1213Tür0813186180 | m² |  | Zimmer- und Holzbauarbeiten | Türöffnung |  | 7.5 | NEW | 1213Wa 0813186186 | AllplanAttributes - Türanschlag: -; Ortscode_Geschoßbezeichnung: E02
Türöffnung | H2 Ebene +2 | 1213Tür0813057876 | m² |  | Zimmer- und Holzbauarbeiten | Türöffnung |  | 7.5 | NEW | 1213Wa 0812985925 | AllplanAttributes - Codetext: Codetext; Türanschlag: DIN R; Attributset-Objekt: OpeningElement; Ortscode_Geschoßbezeichnung: E02; Pset_OpeningElementCommon - FireExit: no; Reference: Codetext
Türöffnung | H2 Ebene +2 | 1213Tür0813196479 | m² | 0 | Zimmer- und Holzbauarbeiten | Türöffnung | 0 | 7.5 | NEW | 1213Wa 0813196455 | AllplanAttributes - Türanschlag: DIN R; Ortscode_Geschoßbezeichnung: E02
Türöffnung | H2 Ebene +2 | 1213Tür0813004487 | m² |  | Zimmer- und Holzbauarbeiten | Türöffnung |  | 7.5 | NEW | 1213Wa 0812986279 | AllplanAttributes - Codetext: Codetext; Türanschlag: DIN L; Attributset-Objekt: OpeningElement; Ortscode_Geschoßbezeichnung: E02; Pset_OpeningElementCommon - FireExit: no; Reference: Codetext
Türöffnung | H2 Ebene +2 | 1213Tür0813098088 | m² | 0 | Zimmer- und Holzbauarbeiten | Türöffnung | 0 | 7.5 | NEW | 1213Wa 0813098072 | AllplanAttributes - Türanschlag: DIN L; Ortscode_Geschoßbezeichnung: E02
Türöffnung | H2 Ebene +2 | 1213Tür0813004577 | m² |  | Zimmer- und Holzbauarbeiten | Türöffnung |  | 7.5 | NEW | 1213Wa 0812985946 | AllplanAttributes - Codetext: Codetext; Türanschlag: -; Attributset-Objekt: OpeningElement; Ortscode_Geschoßbezeichnung: E02; Pset_OpeningElementCommon - FireExit: no; Reference: Codetext
Türöffnung | H2 Ebene +2 | 1213Tür0813090708 | m² | 0 | Zimmer- und Holzbauarbeiten | Türöffnung | 0 | 7.5 | NEW | 1213Wa 0813090386 | AllplanAttributes - Türanschlag: -; Ortscode_Geschoßbezeichnung: E02
Türöffnung | H2 Ebene +2 | 1213Tür0813580093 | m² |  | Zimmer- und Holzbauarbeiten | Türöffnung |  | 7.5 | NEW | 1213Wa 0812985946 | AllplanAttributes - Codetext: Codetext; Türanschlag: -; Attributset-Objekt: OpeningElement; Ortscode_Geschoßbezeichnung: E02; Pset_OpeningElementCommon - FireExit: no; Reference: Codetext
Türöffnung | H2 Ebene +2 | 1213Tür0813580105 | m² |  | Zimmer- und Holzbauarbeiten | Türöffnung |  | 7.5 | NEW | 1213Wa 0812985946 | AllplanAttributes - Codetext: Codetext; Türanschlag: -; Attributset-Objekt: OpeningElement; Ortscode_Geschoßbezeichnung: E02; Pset_OpeningElementCommon - FireExit: no; Reference: Codetext
Türöffnung | H2 Ebene +2 | 1213Tür0813580114 | m² | 0 | Zimmer- und Holzbauarbeiten | Türöffnung | 0 | 7.5 | NEW | 1213Wa 0813090386 | AllplanAttributes - Türanschlag: -; Ortscode_Geschoßbezeichnung: E02
Türöffnung | H2 Ebene +2 | 1213Tür0813580110 | m² | 0 | Zimmer- und Holzbauarbeiten | Türöffnung | 0 | 7.5 | NEW | 1213Wa 0813090386 | AllplanAttributes - Türanschlag: -; Ortscode_Geschoßbezeichnung: E02
Türöffnung | H2 Ebene +2 | 1213Tür0813580867 | m² |  | Zimmer- und Holzbauarbeiten | Türöffnung |  | 7.5 | NEW | 1213Wa 0812985946 | AllplanAttributes - Codetext: Codetext; Türanschlag: -; Attributset-Objekt: OpeningElement; Ortscode_Geschoßbezeichnung: E02; Pset_OpeningElementCommon - FireExit: no; Reference: Codetext
Türöffnung | H2 Ebene +2 | 1213Tür0813580876 | m² |  | Zimmer- und Holzbauarbeiten | Türöffnung |  | 7.5 | NEW | 1213Wa 0812985946 | AllplanAttributes - Codetext: Codetext; Türanschlag: -; Attributset-Objekt: OpeningElement; Ortscode_Geschoßbezeichnung: E02; Pset_OpeningElementCommon - FireExit: no; Reference: Codetext
Türöffnung | H2 Ebene +2 | 1213Tür0813580859 | m² | 0 | Zimmer- und Holzbauarbeiten | Türöffnung | 0 | 7.5 | NEW | 1213Wa 0813090386 | AllplanAttributes - Türanschlag: -; Ortscode_Geschoßbezeichnung: E02
Türöffnung | H2 Ebene +2 | 1213Tür0813580862 | m² | 0 | Zimmer- und Holzbauarbeiten | Türöffnung | 0 | 7.5 | NEW | 1213Wa 0813090386 | AllplanAttributes - Türanschlag: -; Ortscode_Geschoßbezeichnung: E02
Türöffnung | H2 Ebene +2 | 1213Tür0813581415 | m² |  | Zimmer- und Holzbauarbeiten | Türöffnung |  | 7.5 | NEW | 1213Wa 0812985946 | AllplanAttributes - Codetext: Codetext; Türanschlag: -; Attributset-Objekt: OpeningElement; Ortscode_Geschoßbezeichnung: E02; Pset_OpeningElementCommon - FireExit: no; Reference: Codetext
Türöffnung | H2 Ebene +2 | 1213Tür0813581421 | m² |  | Zimmer- und Holzbauarbeiten | Türöffnung |  | 7.5 | NEW | 1213Wa 0812985946 | AllplanAttributes - Codetext: Codetext; Türanschlag: -; Attributset-Objekt: OpeningElement; Ortscode_Geschoßbezeichnung: E02; Pset_OpeningElementCommon - FireExit: no; Reference: Codetext
Türöffnung | H2 Ebene +2 | 1213Tür0813581411 | m² | 0 | Zimmer- und Holzbauarbeiten | Türöffnung | 0 | 7.5 | NEW | 1213Wa 0813090386 | AllplanAttributes - Türanschlag: -; Ortscode_Geschoßbezeichnung: E02
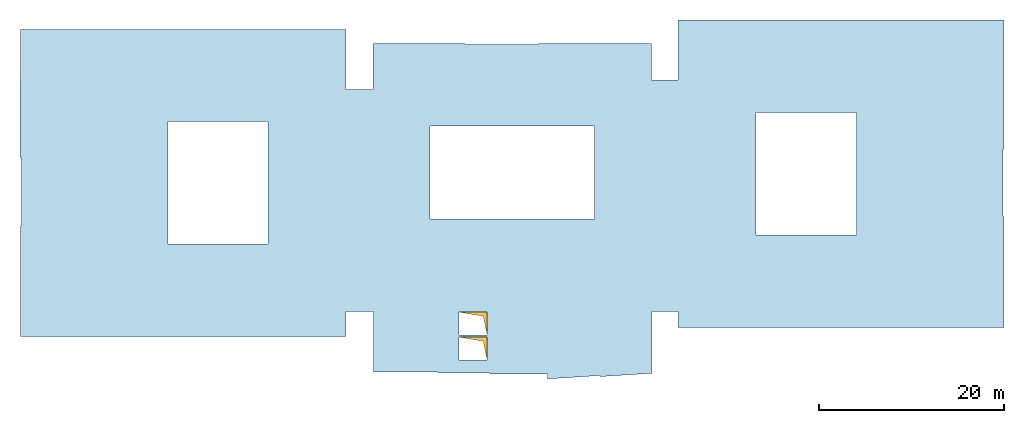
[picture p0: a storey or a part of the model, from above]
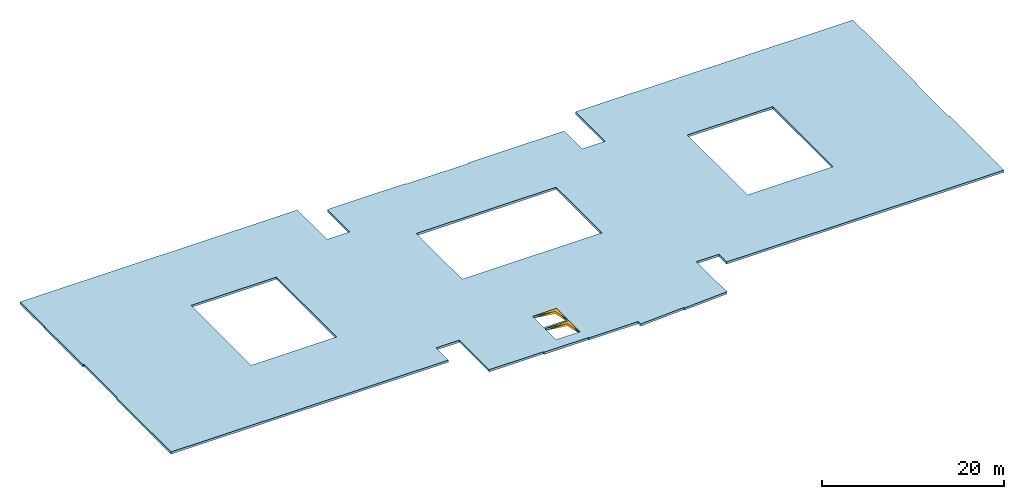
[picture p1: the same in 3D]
Properties of the parts of a building model (IFC4), part 34 of 80

# IfcOpeningElement: Opening (3497)
Name | In | Allright_Bauteil_ID | Abrechnungsart | Versatz_oben | Gewerk | Objektname | Versatz_unten | OKFF | Status | P_ID | AllplanAttributes, Feuerwiderstandsklasse | Sicherheitsklasse | g-Wert
Türöffnung | H2 Ebene +2 | 1213Tür0813581413 | m² | 0 | Zimmer- und Holzbauarbeiten | Türöffnung | 0 | 7.5 | NEW | 1213Wa 0813090386 | AllplanAttributes - Türanschlag: -; Ortscode_Geschoßbezeichnung: E02
Türöffnung | H2 Ebene +2 | 1213Tür0813004613 | m² |  | Zimmer- und Holzbauarbeiten | Türöffnung |  | 7.5 | NEW | 1213Wa 0812986616 | AllplanAttributes - Codetext: Codetext; Türanschlag: -; Attributset-Objekt: OpeningElement; Ortscode_Geschoßbezeichnung: E02; Pset_OpeningElementCommon - FireExit: no; Reference: Codetext
Türöffnung | H2 Ebene +2 | 1213Tür0813089583 | m² | 0 | Zimmer- und Holzbauarbeiten | Türöffnung | 0 | 7.5 | NEW | 1213Wa 0813089415 | AllplanAttributes - Türanschlag: -; Ortscode_Geschoßbezeichnung: E02
Türöffnung | H2 Ebene +2 | 1213Tür0813592927 | m² |  | Zimmer- und Holzbauarbeiten | Türöffnung |  | 7.5 | NEW | 1213Wa 0812986616 | AllplanAttributes - Codetext: Codetext; Türanschlag: -; Attributset-Objekt: OpeningElement; Ortscode_Geschoßbezeichnung: E02; Pset_OpeningElementCommon - FireExit: no; Reference: Codetext
Türöffnung | H2 Ebene +2 | 1213Tür0813592931 | m² |  | Zimmer- und Holzbauarbeiten | Türöffnung |  | 7.5 | NEW | 1213Wa 0812986616 | AllplanAttributes - Codetext: Codetext; Türanschlag: -; Attributset-Objekt: OpeningElement; Ortscode_Geschoßbezeichnung: E02; Pset_OpeningElementCommon - FireExit: no; Reference: Codetext
Türöffnung | H2 Ebene +2 | 1213Tür0813592920 | m² | 0 | Zimmer- und Holzbauarbeiten | Türöffnung | 0 | 7.5 | NEW | 1213Wa 0813089415 | AllplanAttributes - Türanschlag: -; Ortscode_Geschoßbezeichnung: E02
Türöffnung | H2 Ebene +2 | 1213Tür0813592924 | m² | 0 | Zimmer- und Holzbauarbeiten | Türöffnung | 0 | 7.5 | NEW | 1213Wa 0813089415 | AllplanAttributes - Türanschlag: -; Ortscode_Geschoßbezeichnung: E02
Türöffnung | H2 Ebene +2 | 1213Tür0813593916 | m² |  | Zimmer- und Holzbauarbeiten | Türöffnung |  | 7.5 | NEW | 1213Wa 0812986616 | - | AllplanAttributes - Codetext: Codetext; Türanschlag: -; Attributset-Objekt: OpeningElement; Rauchschutz: no; Selbstschließend: no; ash T_Unterschnitt: -; ash T_Zulage Schachttür: no; ash T_Dichtschließend: yes; ash T_Feststellanlage (FSA): -; ash T_nicht abschließbar: no; Ortscode_Geschoßbezeichnung: E02; Pset_OpeningElementCommon - FireExit: no; Reference: Codetext
Türöffnung | H2 Ebene +2 | 1213Tür0813593920 | m² |  | Zimmer- und Holzbauarbeiten | Türöffnung |  | 7.5 | NEW | 1213Wa 0812986616 | AllplanAttributes - Codetext: Codetext; Türanschlag: -; Attributset-Objekt: OpeningElement; Ortscode_Geschoßbezeichnung: E02; Pset_OpeningElementCommon - FireExit: no; Reference: Codetext
Türöffnung | H2 Ebene +2 | 1213Tür0813593910 | m² | 0 | Zimmer- und Holzbauarbeiten | Türöffnung | 0 | 7.5 | NEW | 1213Wa 0813089415 | AllplanAttributes - Türanschlag: -; Ortscode_Geschoßbezeichnung: E02
Türöffnung | H2 Ebene +2 | 1213Tür0813593911 | m² | 0 | Zimmer- und Holzbauarbeiten | Türöffnung | 0 | 7.5 | NEW | 1213Wa 0813089415 | AllplanAttributes - Türanschlag: -; Ortscode_Geschoßbezeichnung: E02
Türöffnung | H2 Ebene +2 | 1213Tür0813594497 | m² |  | Zimmer- und Holzbauarbeiten | Türöffnung |  | 7.5 | NEW | 1213Wa 0812986616 | - | AllplanAttributes - Codetext: Codetext; Türanschlag: -; Attributset-Objekt: OpeningElement; Rauchschutz: no; Selbstschließend: no; ash T_Unterschnitt: -; ash T_Zulage Schachttür: no; ash T_Dichtschließend: yes; ash T_Feststellanlage (FSA): -; ash T_nicht abschließbar: no; Ortscode_Geschoßbezeichnung: E02; Pset_OpeningElementCommon - FireExit: no; Reference: Codetext
Türöffnung | H2 Ebene +2 | 1213Tür0813594493 | m² |  | Zimmer- und Holzbauarbeiten | Türöffnung |  | 7.5 | NEW | 1213Wa 0812986616 | AllplanAttributes - Codetext: Codetext; Türanschlag: -; Attributset-Objekt: OpeningElement; Ortscode_Geschoßbezeichnung: E02; Pset_OpeningElementCommon - FireExit: no; Reference: Codetext
2 x Türöffnung | H2 Ebene +2 | 1213Tür0813594484 | m² | 0 | Zimmer- und Holzbauarbeiten | Türöffnung | 0 | 7.5 | NEW | 1213Wa 0813089415 | AllplanAttributes - Türanschlag: -; Ortscode_Geschoßbezeichnung: E02
2 x Türöffnung | H2 Ebene +2 | 1213Tür0813594483 | m² | 0 | Zimmer- und Holzbauarbeiten | Türöffnung | 0 | 7.5 | NEW | 1213Wa 0813089415 | AllplanAttributes - Türanschlag: -; Ortscode_Geschoßbezeichnung: E02
2 x Türöffnung | H2 Ebene +2 | 1213Tür0813004280 | m² |  | Zimmer- und Holzbauarbeiten | Türöffnung |  | 7.5 | NEW | 1213Wa 0812986209 | - | AllplanAttributes - Codetext: Codetext; Türanschlag: -; Attributset-Objekt: OpeningElement; Rauchschutz: no; Selbstschließend: no; ash T_Unterschnitt: -; ash T_Zulage Schachttür: no; ash T_Dichtschließend: yes; ash T_Feststellanlage (FSA): -; ash T_nicht abschließbar: no; Ortscode_Geschoßbezeichnung: E02; Pset_OpeningElementCommon - FireExit: no; Reference: Codetext
2 x Türöffnung | H2 Ebene +2 | 1213Tür0813004286 | m² |  | Zimmer- und Holzbauarbeiten | Türöffnung |  | 7.5 | NEW | 1213Wa 0812986209 | - | AllplanAttributes - Codetext: Codetext; Türanschlag: -; Attributset-Objekt: OpeningElement; Rauchschutz: no; Selbstschließend: no; ash T_Unterschnitt: -; ash T_Zulage Schachttür: no; ash T_Dichtschließend: yes; ash T_Feststellanlage (FSA): -; ash T_nicht abschließbar: no; Ortscode_Geschoßbezeichnung: E02; Pset_OpeningElementCommon - FireExit: no; Reference: Codetext
Türöffnung | H2 Ebene +2 | 1213Tür0813083029 | m² | 0 | Zimmer- und Holzbauarbeiten | Türöffnung | 0 | 7.5 | NEW | 1213Wa 0813082944 | AllplanAttributes - Türanschlag: -; Ortscode_Geschoßbezeichnung: E02
Türöffnung | H2 Ebene +2 | 1213Tür0813082952 | m² | 0 | Zimmer- und Holzbauarbeiten | Türöffnung | 0 | 7.5 | NEW | 1213Wa 0813082944 | AllplanAttributes - Türanschlag: -; Ortscode_Geschoßbezeichnung: E02
Türöffnung | H2 Ebene +2 | 1213Tür0813622248 | m² |  | Zimmer- und Holzbauarbeiten | Türöffnung |  | 7.5 | NEW | 1213Wa 0812986209 | - | AllplanAttributes - Codetext: Codetext; Türanschlag: -; Attributset-Objekt: OpeningElement; Rauchschutz: no; Selbstschließend: no; ash T_Unterschnitt: -; ash T_Zulage Schachttür: no; ash T_Dichtschließend: yes; ash T_Feststellanlage (FSA): -; ash T_nicht abschließbar: no; Ortscode_Geschoßbezeichnung: E02; Pset_OpeningElementCommon - FireExit: no; Reference: Codetext
Türöffnung | H2 Ebene +2 | 1213Tür0813622254 | m² |  | Zimmer- und Holzbauarbeiten | Türöffnung |  | 7.5 | NEW | 1213Wa 0812986209 | - | AllplanAttributes - Codetext: Codetext; Türanschlag: -; Attributset-Objekt: OpeningElement; Rauchschutz: no; Selbstschließend: no; ash T_Unterschnitt: -; ash T_Zulage Schachttür: no; ash T_Dichtschließend: yes; ash T_Feststellanlage (FSA): -; ash T_nicht abschließbar: no; Ortscode_Geschoßbezeichnung: E02; Pset_OpeningElementCommon - FireExit: no; Reference: Codetext
Türöffnung | H2 Ebene +2 | 1213Tür0813622241 | m² | 0 | Zimmer- und Holzbauarbeiten | Türöffnung | 0 | 7.5 | NEW | 1213Wa 0813082944 | AllplanAttributes - Türanschlag: -; Ortscode_Geschoßbezeichnung: E02
Türöffnung | H2 Ebene +2 | 1213Tür0813622247 | m² | 0 | Zimmer- und Holzbauarbeiten | Türöffnung | 0 | 7.5 | NEW | 1213Wa 0813082944 | AllplanAttributes - Türanschlag: -; Ortscode_Geschoßbezeichnung: E02
Türöffnung | H2 Ebene +2 | 1213Tür0813623055 | m² |  | Zimmer- und Holzbauarbeiten | Türöffnung |  | 7.5 | NEW | 1213Wa 0812986209 | - | AllplanAttributes - Codetext: Codetext; Türanschlag: -; Attributset-Objekt: OpeningElement; Rauchschutz: no; Selbstschließend: no; ash T_Unterschnitt: -; ash T_Zulage Schachttür: no; ash T_Dichtschließend: yes; ash T_Feststellanlage (FSA): -; ash T_nicht abschließbar: no; Ortscode_Geschoßbezeichnung: E02; Pset_OpeningElementCommon - FireExit: no; Reference: Codetext
Türöffnung | H2 Ebene +2 | 1213Tür0813623059 | m² |  | Zimmer- und Holzbauarbeiten | Türöffnung |  | 7.5 | NEW | 1213Wa 0812986209 | - | AllplanAttributes - Codetext: Codetext; Türanschlag: -; Attributset-Objekt: OpeningElement; Rauchschutz: no; Selbstschließend: no; ash T_Unterschnitt: -; ash T_Zulage Schachttür: no; ash T_Dichtschließend: yes; ash T_Feststellanlage (FSA): -; ash T_nicht abschließbar: no; Ortscode_Geschoßbezeichnung: E02; Pset_OpeningElementCommon - FireExit: no; Reference: Codetext
Türöffnung | H2 Ebene +2 | 1213Tür0813623047 | m² | 0 | Zimmer- und Holzbauarbeiten | Türöffnung | 0 | 7.5 | NEW | 1213Wa 0813082944 | AllplanAttributes - Türanschlag: -; Ortscode_Geschoßbezeichnung: E02
Türöffnung | H2 Ebene +2 | 1213Tür0813623048 | m² | 0 | Zimmer- und Holzbauarbeiten | Türöffnung | 0 | 7.5 | NEW | 1213Wa 0813082944 | AllplanAttributes - Türanschlag: -; Ortscode_Geschoßbezeichnung: E02
Türöffnung | H2 Ebene +2 | 1213Tür0813623478 | m² |  | Zimmer- und Holzbauarbeiten | Türöffnung |  | 7.5 | NEW | 1213Wa 0812986209 | - | AllplanAttributes - Codetext: Codetext; Türanschlag: -; Attributset-Objekt: OpeningElement; Rauchschutz: no; Selbstschließend: no; ash T_Unterschnitt: -; ash T_Zulage Schachttür: no; ash T_Dichtschließend: yes; ash T_Feststellanlage (FSA): -; ash T_nicht abschließbar: no; Ortscode_Geschoßbezeichnung: E02; Pset_OpeningElementCommon - FireExit: no; Reference: Codetext
Türöffnung | H2 Ebene +2 | 1213Tür0813623469 | m² | 0 | Zimmer- und Holzbauarbeiten | Türöffnung | 0 | 7.5 | NEW | 1213Wa 0813082944 | AllplanAttributes - Türanschlag: -; Ortscode_Geschoßbezeichnung: E02
Türöffnung | H2 Ebene +2 | 1213Tür0813635043 | m² |  | Zimmer- und Holzbauarbeiten | Türöffnung |  | 7.5 | NEW | 1213Wa 0812986194 | - | AllplanAttributes - Codetext: Codetext; Türanschlag: -; Attributset-Objekt: OpeningElement; Rauchschutz: no; Selbstschließend: no; ash T_Unterschnitt: -; ash T_Zulage Schachttür: no; ash T_Dichtschließend: yes; ash T_Feststellanlage (FSA): -; ash T_nicht abschließbar: no; Ortscode_Geschoßbezeichnung: E02; Pset_OpeningElementCommon - FireExit: no; Reference: Codetext
Türöffnung | H2 Ebene +2 | 1213Tür0813635036 | m² | 0 | Zimmer- und Holzbauarbeiten | Türöffnung | 0 | 7.5 | NEW | 1213Wa 0813082013 | AllplanAttributes - Türanschlag: -; Ortscode_Geschoßbezeichnung: E02
Türöffnung | H2 Ebene +2 | 1213Tür0813636002 | m² |  | Zimmer- und Holzbauarbeiten | Türöffnung |  | 7.5 | NEW | 1213Wa 0812986194 | - | AllplanAttributes - Codetext: Codetext; Türanschlag: -; Attributset-Objekt: OpeningElement; Rauchschutz: no; Selbstschließend: no; ash T_Unterschnitt: -; ash T_Zulage Schachttür: no; ash T_Dichtschließend: yes; ash T_Feststellanlage (FSA): -; ash T_nicht abschließbar: no; Ortscode_Geschoßbezeichnung: E02; Pset_OpeningElementCommon - FireExit: no; Reference: Codetext
Türöffnung | H2 Ebene +2 | 1213Tür0813636006 | m² |  | Zimmer- und Holzbauarbeiten | Türöffnung |  | 7.5 | NEW | 1213Wa 0812986194 | - | AllplanAttributes - Codetext: Codetext; Türanschlag: -; Attributset-Objekt: OpeningElement; Rauchschutz: no; Selbstschließend: no; ash T_Unterschnitt: -; ash T_Zulage Schachttür: no; ash T_Dichtschließend: yes; ash T_Feststellanlage (FSA): -; ash T_nicht abschließbar: no; Ortscode_Geschoßbezeichnung: E02; Pset_OpeningElementCommon - FireExit: no; Reference: Codetext
Türöffnung | H2 Ebene +2 | 1213Tür0813635987 | m² | 0 | Zimmer- und Holzbauarbeiten | Türöffnung | 0 | 7.5 | NEW | 1213Wa 0813082013 | AllplanAttributes - Türanschlag: -; Ortscode_Geschoßbezeichnung: E02
Türöffnung | H2 Ebene +2 | 1213Tür0813635988 | m² | 0 | Zimmer- und Holzbauarbeiten | Türöffnung | 0 | 7.5 | NEW | 1213Wa 0813082013 | AllplanAttributes - Türanschlag: -; Ortscode_Geschoßbezeichnung: E02
2 x Türöffnung | H2 Ebene +2 | 1213Tür0813004424 | m² |  | Zimmer- und Holzbauarbeiten | Türöffnung |  | 7.5 | NEW | 1213Wa 0812986194 | - | AllplanAttributes - Codetext: Codetext; Türanschlag: -; Attributset-Objekt: OpeningElement; Rauchschutz: no; Selbstschließend: no; ash T_Unterschnitt: -; ash T_Zulage Schachttür: no; ash T_Dichtschließend: yes; ash T_Feststellanlage (FSA): -; ash T_nicht abschließbar: no; Ortscode_Geschoßbezeichnung: E02; Pset_OpeningElementCommon - FireExit: no; Reference: Codetext
2 x Türöffnung | H2 Ebene +2 | 1213Tür0813004394 | m² |  | Zimmer- und Holzbauarbeiten | Türöffnung |  | 7.5 | NEW | 1213Wa 0812986194 | - | AllplanAttributes - Codetext: Codetext; Türanschlag: -; Attributset-Objekt: OpeningElement; Rauchschutz: no; Selbstschließend: no; ash T_Unterschnitt: -; ash T_Zulage Schachttür: no; ash T_Dichtschließend: yes; ash T_Feststellanlage (FSA): -; ash T_nicht abschließbar: no; Ortscode_Geschoßbezeichnung: E02; Pset_OpeningElementCommon - FireExit: no; Reference: Codetext
Türöffnung | H2 Ebene +2 | 1213Tür0813082255 | m² | 0 | Zimmer- und Holzbauarbeiten | Türöffnung | 0 | 7.5 | NEW | 1213Wa 0813082013 | AllplanAttributes - Türanschlag: -; Ortscode_Geschoßbezeichnung: E02
Türöffnung | H2 Ebene +2 | 1213Tür0813082563 | m² | 0 | Zimmer- und Holzbauarbeiten | Türöffnung | 0 | 7.5 | NEW | 1213Wa 0813082013 | AllplanAttributes - Türanschlag: -; Ortscode_Geschoßbezeichnung: E02
Türöffnung | H2 Ebene +2 | 1213Tür0813636630 | m² |  | Zimmer- und Holzbauarbeiten | Türöffnung |  | 7.5 | NEW | 1213Wa 0812986194 | - | AllplanAttributes - Codetext: Codetext; Türanschlag: -; Attributset-Objekt: OpeningElement; Rauchschutz: no; Selbstschließend: no; ash T_Unterschnitt: -; ash T_Zulage Schachttür: no; ash T_Dichtschließend: yes; ash T_Feststellanlage (FSA): -; ash T_nicht abschließbar: no; Ortscode_Geschoßbezeichnung: E02; Pset_OpeningElementCommon - FireExit: no; Reference: Codetext
Türöffnung | H2 Ebene +2 | 1213Tür0813636638 | m² |  | Zimmer- und Holzbauarbeiten | Türöffnung |  | 7.5 | NEW | 1213Wa 0812986194 | - | AllplanAttributes - Codetext: Codetext; Türanschlag: -; Attributset-Objekt: OpeningElement; Rauchschutz: no; Selbstschließend: no; ash T_Unterschnitt: -; ash T_Zulage Schachttür: no; ash T_Dichtschließend: yes; ash T_Feststellanlage (FSA): -; ash T_nicht abschließbar: no; Ortscode_Geschoßbezeichnung: E02; Pset_OpeningElementCommon - FireExit: no; Reference: Codetext
Türöffnung | H2 Ebene +2 | 1213Tür0813636623 | m² | 0 | Zimmer- und Holzbauarbeiten | Türöffnung | 0 | 7.5 | NEW | 1213Wa 0813082013 | AllplanAttributes - Türanschlag: -; Ortscode_Geschoßbezeichnung: E02
Türöffnung | H2 Ebene +2 | 1213Tür0813636625 | m² | 0 | Zimmer- und Holzbauarbeiten | Türöffnung | 0 | 7.5 | NEW | 1213Wa 0813082013 | AllplanAttributes - Türanschlag: -; Ortscode_Geschoßbezeichnung: E02
Fensteröffnung | H2 Ebene +2 | 1213Fen0812969882 | m² |  | Fensterarbeiten | Fensteröffnung |  | 7.5 |  | 1213Wa 0812971219 | AllplanAttributes - Ortscode_Geschoßbezeichnung: E02
Fensteröffnung | H2 Ebene +2 | 1213Fen0813086679 | m² | 0 | Fensterarbeiten | Fensteröffnung | 0 | 7.5 | NEW | 1213Wa 0813086661 | AllplanAttributes - Ortscode_Geschoßbezeichnung: E02
Fensteröffnung | H2 Ebene +2 | 1213Fen0813086680 | m² | 0 | Fensterarbeiten | Fensteröffnung | 0 | 7.5 | NEW | 1213Wa 0813086662 | AllplanAttributes - ash D_Detailverweis: D1833; Ortscode_Geschoßbezeichnung: E02
Türöffnung | H2 Ebene +2 | 1213Tür0813004738 | m² |  | Zimmer- und Holzbauarbeiten | Türöffnung |  | 7.5 | NEW | 1213Wa 0812985908 | AllplanAttributes - Codetext: Codetext; Türanschlag: DIN R; Attributset-Objekt: OpeningElement; Ortscode_Geschoßbezeichnung: E02; Pset_OpeningElementCommon - FireExit: no; Reference: Codetext
Türöffnung | H2 Ebene +2 | 1213Tür0813087796 | m² | 0 | Zimmer- und Holzbauarbeiten | Türöffnung | 0 | 7.5 | NEW | 1213Wa 0813087773 | AllplanAttributes - Türanschlag: DIN R; Ortscode_Geschoßbezeichnung: E02
Türöffnung | H2 Ebene +2 | 1213Tür0813099037 | m² | 0 | Zimmer- und Holzbauarbeiten | Türöffnung | 0 | 7.5 | NEW | 1213Wa 0813099003 | AllplanAttributes - Türanschlag: DIN R; Ortscode_Geschoßbezeichnung: E02
Türöffnung | H2 Ebene +2 | 1213Tür0813240139 | m² |  | Zimmer- und Holzbauarbeiten | Türöffnung |  | 7.5 | NEW | 1213Wa 0812985956 | AllplanAttributes - Codetext: Codetext; Türanschlag: DIN R; Attributset-Objekt: OpeningElement; Ortscode_Geschoßbezeichnung: E02; Pset_OpeningElementCommon - FireExit: no; Reference: Codetext
Türöffnung | H2 Ebene +2 | 1213Tür0813240148 | m² | 0 | Zimmer- und Holzbauarbeiten | Türöffnung | 0 | 7.5 | NEW | 1213Wa 0813079805 | AllplanAttributes - Türanschlag: DIN R; Ortscode_Geschoßbezeichnung: E02
Türöffnung | H2 Ebene +2 | 1213Tür0813240151 | m² | 0 | Zimmer- und Holzbauarbeiten | Türöffnung | 0 | 7.5 | NEW | 1213Wa 0813079806 | AllplanAttributes - Türanschlag: DIN R; Ortscode_Geschoßbezeichnung: E02
Türöffnung | H2 Ebene +2 | 1213Tür0813245397 | m² |  | Zimmer- und Holzbauarbeiten | Türöffnung |  | 7.5 | NEW | 1213Wa 0812985956 | AllplanAttributes - Codetext: Codetext; Türanschlag: DIN L; Attributset-Objekt: OpeningElement; Ortscode_Geschoßbezeichnung: E02; Pset_OpeningElementCommon - FireExit: no; Reference: Codetext
Türöffnung | H2 Ebene +2 | 1213Tür0813245392 | m² | 0 | Zimmer- und Holzbauarbeiten | Türöffnung | 0 | 7.5 | NEW | 1213Wa 0813079805 | AllplanAttributes - Türanschlag: DIN L; Ortscode_Geschoßbezeichnung: E02
Türöffnung | H2 Ebene +2 | 1213Tür0813245389 | m² | 0 | Zimmer- und Holzbauarbeiten | Türöffnung | 0 | 7.5 | NEW | 1213Wa 0813079806 | AllplanAttributes - Türanschlag: DIN L; Ortscode_Geschoßbezeichnung: E02
Türöffnung | H2 Ebene +2 | 1213Tür0813239228 | m² |  | Zimmer- und Holzbauarbeiten | Türöffnung |  | 7.5 | NEW | 1213Wa 0812985956 | AllplanAttributes - Codetext: Codetext; Türanschlag: DIN L; Attributset-Objekt: OpeningElement; Ortscode_Geschoßbezeichnung: E02; Pset_OpeningElementCommon - FireExit: no; Reference: Codetext
Türöffnung | H2 Ebene +2 | 1213Tür0813239226 | m² | 0 | Zimmer- und Holzbauarbeiten | Türöffnung | 0 | 7.5 | NEW | 1213Wa 0813079805 | AllplanAttributes - Türanschlag: DIN L; Ortscode_Geschoßbezeichnung: E02
Türöffnung | H2 Ebene +2 | 1213Tür0813239219 | m² | 0 | Zimmer- und Holzbauarbeiten | Türöffnung | 0 | 7.5 | NEW | 1213Wa 0813079806 | AllplanAttributes - Türanschlag: DIN L; Ortscode_Geschoßbezeichnung: E02
Türöffnung | H2 Ebene +2 | 1213Tür0813004352 | m² |  | Zimmer- und Holzbauarbeiten | Türöffnung |  | 7.5 | NEW | 1213Wa 0812985956 | AllplanAttributes - Codetext: Codetext; Türanschlag: DIN L; Attributset-Objekt: OpeningElement; Ortscode_Geschoßbezeichnung: E02; Pset_OpeningElementCommon - FireExit: no; Reference: Codetext
Türöffnung | H2 Ebene +2 | 1213Tür0813079820 | m² | 0 | Zimmer- und Holzbauarbeiten | Türöffnung | 0 | 7.5 | NEW | 1213Wa 0813079805 | AllplanAttributes - Türanschlag: DIN L; Ortscode_Geschoßbezeichnung: E02
Türöffnung | H2 Ebene +2 | 1213Tür0813079821 | m² | 0 | Zimmer- und Holzbauarbeiten | Türöffnung | 0 | 7.5 | NEW | 1213Wa 0813079806 | AllplanAttributes - Türanschlag: DIN L; Ortscode_Geschoßbezeichnung: E02
Türöffnung | H2 Ebene +2 | 1213Tür0813004471 | m² |  | Zimmer- und Holzbauarbeiten | Türöffnung |  | 7.5 | NEW | 1213Wa 0812986131 | AllplanAttributes - Codetext: Codetext; Türanschlag: DIN L; Attributset-Objekt: OpeningElement; Ortscode_Geschoßbezeichnung: E02; Pset_OpeningElementCommon - FireExit: no; Reference: Codetext
Türöffnung | H2 Ebene +2 | 1213Tür0813084573 | m² | 0 | Zimmer- und Holzbauarbeiten | Türöffnung | 0 | 7.5 | NEW | 1213Wa 0813084562 | AllplanAttributes - Türanschlag: DIN L; Ortscode_Geschoßbezeichnung: E02
Türöffnung | H2 Ebene +2 | 1213Tür0813096637 | m² | 0 | Zimmer- und Holzbauarbeiten | Türöffnung | 0 | 7.5 | NEW | 1213Wa 0813096617 | AllplanAttributes - Türanschlag: DIN L; Ortscode_Geschoßbezeichnung: E02
Türöffnung | H2 Ebene +2 | 1213Tür0813004205 | m² |  | Zimmer- und Holzbauarbeiten | Türöffnung |  | 7.5 | NEW | 1213Wa 0812986420 | AllplanAttributes - Codetext: Codetext; Türanschlag: DIN L; Attributset-Objekt: OpeningElement; Ortscode_Geschoßbezeichnung: E02; Pset_OpeningElementCommon - FireExit: no; Reference: Codetext
Türöffnung | H2 Ebene +2 | 1213Tür0813196268 | m² | 0 | Zimmer- und Holzbauarbeiten | Türöffnung | 0 | 7.5 | NEW | 1213Wa 0813196247 | AllplanAttributes - Türanschlag: DIN L; Ortscode_Geschoßbezeichnung: E02
Türöffnung | H2 Ebene +2 | 1213Tür0813004144 | m² |  | Trockenbauarbeiten | Türöffnung |  | 7.5 | NEW | 1213Wa 0812985983 | AllplanAttributes - Codetext: Codetext; Türanschlag: DIN L; Attributset-Objekt: OpeningElement; Ortscode_Geschoßbezeichnung: E02; Pset_OpeningElementCommon - FireExit: no; Reference: Codetext
Türöffnung | H2 Ebene +2 | 1213Tür0813197019 | m² | 0 | Trockenbauarbeiten | Türöffnung | 0 | 7.5 | NEW | 1213Wa 0813197001 | AllplanAttributes - Türanschlag: DIN L; Ortscode_Geschoßbezeichnung: E02
Türöffnung | H2 Ebene +2 | 1213Tür0813004732 | m² |  | Zimmer- und Holzbauarbeiten | Türöffnung |  | 7.5 | NEW | 1213Wa 0812986184 | AllplanAttributes - Codetext: Codetext; Türanschlag: DIN R; Attributset-Objekt: OpeningElement; Ortscode_Geschoßbezeichnung: E02; Pset_OpeningElementCommon - FireExit: no; Reference: Codetext
Türöffnung | H2 Ebene +2 | 1213Tür0813092567 | m² | 0 | Zimmer- und Holzbauarbeiten | Türöffnung | 0 | 7.5 | NEW | 1213Wa 0813092550 | AllplanAttributes - Türanschlag: DIN R; Ortscode_Geschoßbezeichnung: E02
Türöffnung | H2 Ebene +2 | 1213Tür0813641457 | m² |  | Zimmer- und Holzbauarbeiten | Türöffnung |  | 7.5 | NEW | 1213Wa 0812986184 | AllplanAttributes - Codetext: Codetext; Türanschlag: DIN L; Attributset-Objekt: OpeningElement; Ortscode_Geschoßbezeichnung: E02; Pset_OpeningElementCommon - FireExit: no; Reference: Codetext
Türöffnung | H2 Ebene +2 | 1213Tür0813641455 | m² | 0 | Zimmer- und Holzbauarbeiten | Türöffnung | 0 | 7.5 | NEW | 1213Wa 0813092550 | AllplanAttributes - Türanschlag: DIN L; Ortscode_Geschoßbezeichnung: E02
Türöffnung | H2 Ebene +2 | 1213Tür0813567290 | m² | 0 | Zimmer- und Holzbauarbeiten | Türöffnung | 0 | 7.5 | NEW | 1113Wa 0812444155 | AllplanAttributes - Türanschlag: DIN R; Positionsnummer_Text: S68; Ortscode_Geschoßbezeichnung: E02
Türöffnung | H2 Ebene +2 | 1213Tür0813567289 | m² | 0 | Zimmer- und Holzbauarbeiten | Türöffnung | 0 | 7.5 | NEW | AllplanAttributes - Türanschlag: DIN R; Ortscode_Geschoßbezeichnung: E02
Türöffnung | H2 Ebene +2 | 1213Tür0813567288 | m² | -30 | Zimmer- und Holzbauarbeiten | Türöffnung | 0 | 7.5 | NEW | AllplanAttributes - Türanschlag: DIN R; Ortscode_Geschoßbezeichnung: E02
Türöffnung | H2 Ebene +2 | 1213Tür0813643222 | m² |  | Zimmer- und Holzbauarbeiten | Türöffnung |  | 7.5 | NEW | 1213Wa 0812986126 | AllplanAttributes - Codetext: Codetext; Türanschlag: DIN L; Attributset-Objekt: OpeningElement; Ortscode_Geschoßbezeichnung: E02; Pset_OpeningElementCommon - FireExit: no; Reference: Codetext
Türöffnung | H2 Ebene +2 | 1213Tür0813643210 | m² |  | Zimmer- und Holzbauarbeiten | Türöffnung |  | 7.5 | NEW | 1213Wa 0812986126 | AllplanAttributes - Codetext: Codetext; Türanschlag: DIN R; Attributset-Objekt: OpeningElement; Ortscode_Geschoßbezeichnung: E02; Pset_OpeningElementCommon - FireExit: no; Reference: Codetext
Türöffnung | H2 Ebene +2 | 1213Tür0813643208 | m² | 0 | Zimmer- und Holzbauarbeiten | Türöffnung | 0 | 7.5 | NEW | 1213Wa 0813091760 | AllplanAttributes - Türanschlag: DIN L; Ortscode_Geschoßbezeichnung: E02
Türöffnung | H2 Ebene +2 | 1213Tür0813643206 | m² | 0 | Zimmer- und Holzbauarbeiten | Türöffnung | 0 | 7.5 | NEW | 1213Wa 0813091760 | AllplanAttributes - Türanschlag: DIN R; Ortscode_Geschoßbezeichnung: E02
Türöffnung | H2 Ebene +2 | 1213Tür0813643229 | m² | 0 | Zimmer- und Holzbauarbeiten | Türöffnung | 0 | 7.5 | NEW | 1213Wa 0813091761 | AllplanAttributes - Türanschlag: DIN R; Ortscode_Geschoßbezeichnung: E02
Türöffnung | H2 Ebene +2 | 1213Tür0813643228 | m² | 0 | Zimmer- und Holzbauarbeiten | Türöffnung | 0 | 7.5 | NEW | 1213Wa 0813091761 | AllplanAttributes - Türanschlag: DIN L; Ortscode_Geschoßbezeichnung: E02
Türöffnung | H2 Ebene +2 | 1213Tür0813642521 | m² |  | Zimmer- und Holzbauarbeiten | Türöffnung |  | 7.5 | NEW | 1213Wa 0812986126 | AllplanAttributes - Codetext: Codetext; Türanschlag: DIN R; Attributset-Objekt: OpeningElement; Ortscode_Geschoßbezeichnung: E02; Pset_OpeningElementCommon - FireExit: no; Reference: Codetext
Türöffnung | H2 Ebene +2 | 1213Tür0813642529 | m² | 0 | Zimmer- und Holzbauarbeiten | Türöffnung | 0 | 7.5 | NEW | 1213Wa 0813091760 | AllplanAttributes - Türanschlag: DIN R; Ortscode_Geschoßbezeichnung: E02
Türöffnung | H2 Ebene +2 | 1213Tür0813642493 | m² | 0 | Zimmer- und Holzbauarbeiten | Türöffnung | 0 | 7.5 | NEW | 1213Wa 0813091761 | AllplanAttributes - Türanschlag: DIN R; Ortscode_Geschoßbezeichnung: E02
Türöffnung | H2 Ebene +2 | 1213Tür0813643696 | m² |  | Zimmer- und Holzbauarbeiten | Türöffnung |  | 7.5 | NEW | 1213Wa 0812986126 | AllplanAttributes - Codetext: Codetext; Türanschlag: DIN R; Attributset-Objekt: OpeningElement; Ortscode_Geschoßbezeichnung: E02; Pset_OpeningElementCommon - FireExit: no; Reference: Codetext
Türöffnung | H2 Ebene +2 | 1213Tür0813643690 | m² | 0 | Zimmer- und Holzbauarbeiten | Türöffnung | 0 | 7.5 | NEW | 1213Wa 0813091760 | AllplanAttributes - Türanschlag: DIN R; Ortscode_Geschoßbezeichnung: E02
Türöffnung | H2 Ebene +2 | 1213Tür0813643688 | m² | 0 | Zimmer- und Holzbauarbeiten | Türöffnung | 0 | 7.5 | NEW | 1213Wa 0813091761 | AllplanAttributes - Türanschlag: DIN R; Ortscode_Geschoßbezeichnung: E02
Türöffnung | H2 Ebene +2 | 1213Tür0813004104 | m² |  | Betonarbeiten | Türöffnung |  | 7.5 | NEW | 1213Wa 0812986041 | REI 90-A1 | AllplanAttributes - Material: WA-STB; Tragendes Bauteil: yes; Brandabschnittsdefinierendes Bauteil: no; Außenliegend: yes; U-Wert: 0; Schallschutzklasse: 0; Codetext: Codetext; Türanschlag: -; Typ: 0; Brennbares Material: no; Brandverhalten: 0; Brandschutzklasse: A; Ortscode_Geschoßbezeichnung: E02; Pset_OpeningElementCommon - Reference: Codetext
Türöffnung | H2 Ebene +2 | 1213Tür0813004503 | m² |  | Trockenbauarbeiten | Türöffnung |  | 7.5 | NEW | 1213Wa 0812986288 | AllplanAttributes - Codetext: Codetext; Türanschlag: -; Attributset-Objekt: OpeningElement; Ortscode_Geschoßbezeichnung: E02; Pset_OpeningElementCommon - FireExit: no; Reference: Codetext
Türöffnung | H2 Ebene +2 | 1213Tür0813004508 | m² |  | Trockenbauarbeiten | Türöffnung |  | 7.5 | NEW | 1213Wa 0812986283 | AllplanAttributes - Codetext: Codetext; Türanschlag: -; Attributset-Objekt: OpeningElement; Ortscode_Geschoßbezeichnung: E02; Pset_OpeningElementCommon - FireExit: no; Reference: Codetext
Türöffnung | H2 Ebene +2 | 1213Tür0813004128 | m² |  | Betonarbeiten | Türöffnung |  | 7.5 | NEW | 1213Wa 0812986009 | REI 90-A1 | AllplanAttributes - Material: WA-STB; Tragendes Bauteil: yes; Brandabschnittsdefinierendes Bauteil: no; Außenliegend: yes; U-Wert: 0; Schallschutzklasse: 0; Codetext: Codetext; Türanschlag: -; Typ: 0; Brennbares Material: no; Brandverhalten: 0; Brandschutzklasse: A; Ortscode_Geschoßbezeichnung: E02; Pset_OpeningElementCommon - Reference: Codetext
Türöffnung | H2 Ebene +2 | 1213Tür0813004292 | m² |  | Trockenbauarbeiten | Türöffnung |  | 7.5 | NEW | 1213Wa 0812986199 | AllplanAttributes - Codetext: Codetext; Türanschlag: -; Attributset-Objekt: OpeningElement; Pset_OpeningElementCommon - FireExit: no; Reference: Codetext
Türöffnung | H2 Ebene +2 | 1213Tür0813004238 | m² |  | Trockenbauarbeiten | Türöffnung |  | 7.5 | NEW | 1213Wa 0812986230 | AllplanAttributes - Codetext: Codetext; Türanschlag: -; Attributset-Objekt: OpeningElement; Ortscode_Geschoßbezeichnung: E02; Pset_OpeningElementCommon - FireExit: no; Reference: Codetext
Türöffnung | H2 Ebene +2 | 1213Tür0813004233 | m² |  | Trockenbauarbeiten | Türöffnung |  | 7.5 | NEW | 1213Wa 0812986235 | AllplanAttributes - Codetext: Codetext; Türanschlag: -; Attributset-Objekt: OpeningElement; Ortscode_Geschoßbezeichnung: E02; Pset_OpeningElementCommon - FireExit: no; Reference: Codetext
Türöffnung | H2 Ebene +2 | 1213Tür0813156106 | m² |  | Zimmer- und Holzbauarbeiten | Türöffnung |  | 7.5 | NEW | 1213Wa 0813156150 | AllplanAttributes - Türanschlag: -; Ortscode_Geschoßbezeichnung: E02
Türöffnung | H2 Ebene +2 | 1213Tür0813004124 | m² |  | Trockenbauarbeiten | Türöffnung |  | 7.5 | NEW | 1213Wa 0812986005 | AllplanAttributes - Türanschlag: -; Ortscode_Geschoßbezeichnung: E02
Türöffnung | H2 Ebene +2 | 1213Tür0813004376 | m² |  | Zimmer- und Holzbauarbeiten | Türöffnung |  | 7.5 | NEW | 1213Wa 0812986117 | AllplanAttributes - Codetext: Codetext; Türanschlag: DIN R; Attributset-Objekt: OpeningElement; Ortscode_Geschoßbezeichnung: E02; Pset_OpeningElementCommon - FireExit: no; Reference: Codetext
Türöffnung | H2 Ebene +2 | 1213Tür0813078595 | m² | 0 | Zimmer- und Holzbauarbeiten | Türöffnung | 0 | 7.5 | NEW | 1213Wa 0813078469 | AllplanAttributes - Türanschlag: DIN R; Ortscode_Geschoßbezeichnung: E02
Türöffnung | H2 Ebene +2 | 1213Tür0813688320 | m² |  | Zimmer- und Holzbauarbeiten | Türöffnung |  | 7.5 | NEW | 1213Wa 0812986117 | AllplanAttributes - Codetext: Codetext; Türanschlag: DIN L; Attributset-Objekt: OpeningElement; Ortscode_Geschoßbezeichnung: E02; Pset_OpeningElementCommon - FireExit: no; Reference: Codetext
Türöffnung | H2 Ebene +2 | 1213Tür0813688329 | m² | 0 | Zimmer- und Holzbauarbeiten | Türöffnung | 0 | 7.5 | NEW | 1213Wa 0813078469 | AllplanAttributes - Türanschlag: DIN L; Ortscode_Geschoßbezeichnung: E02
Türöffnung | H2 Ebene +2 | 1213Tür0813004130 | m² |  | Trockenbauarbeiten | Türöffnung |  | 7.5 | NEW | 1213Wa 0812986099 | AllplanAttributes - Türanschlag: -; Ortscode_Geschoßbezeichnung: E02
Türöffnung | H2 Ebene +2 | 1213Tür0813005051 | m² |  | Zimmer- und Holzbauarbeiten | Türmakro |  | 7.5 | NEW | 1213Wa 0812986389 | AllplanAttributes - Material: TI-1F-UZ-D; Codetext: Codetext; Türanschlag: DIN L; Attributset-Objekt: Door; Glasanteil_berücksichtigen: 100; ash T_Zulage Schachttür: no; ash T_Dichtschließend: no; ash T_Zarge_Typ: U; ash T_Erforderl. Durchgangsbreite: 0 m; ash T_Türblatt sichtbar 2D: ja; ash T_Feststellanlage (FSA): -; ash T_nicht abschließbar: no; ash T_Tür-Nr.: Innentür 1; ash T_Blatt_Oberfläche: -; ash T_Erford. Durgangshöhe: 0 m; ash T_Blatt_Material: -; ash T_Schallschutz: -; ash T_Zarge_Material: S; ash T_Raum zugehörigkeit: BS; Pset_OpeningElementCommon - FireExit: no; Reference: Codetext; DoorCommon - Außenliegend: no; Feuerwiderstandsklasse: EI2 30; Rauchschutz: yes; Selbstschließend: yes
Türöffnung | H2 Ebene +2 | 1213Tür0813005045 | m² |  | Zimmer- und Holzbauarbeiten | Türmakro |  | 7.5 | NEW | 1213Wa 0812986389 | AllplanAttributes - Material: TI-1F-UZ-D; Codetext: Codetext; Türanschlag: DIN R; Attributset-Objekt: Door; Glasanteil_berücksichtigen: 100; ash T_Zulage Schachttür: no; ash T_Dichtschließend: no; ash T_Zarge_Typ: U; ash T_Erforderl. Durchgangsbreite: 0 m; ash T_Türblatt sichtbar 2D: ja; ash T_Feststellanlage (FSA): -; ash T_nicht abschließbar: no; ash T_Tür-Nr.: Innentür 1; ash T_Blatt_Oberfläche: -; ash T_Erford. Durgangshöhe: 0 m; ash T_Blatt_Material: -; ash T_Schallschutz: -; ash T_Zarge_Material: S; ash T_Raum zugehörigkeit: BS; Pset_OpeningElementCommon - FireExit: no; Reference: Codetext; DoorCommon - Außenliegend: no; Feuerwiderstandsklasse: EI2 30; Rauchschutz: yes; Selbstschließend: yes
Türöffnung | H2 Ebene +2 | 1213Tür0813690461 | m² | 0 | Zimmer- und Holzbauarbeiten | Türöffnung | 0 | 7.5 | NEW | AllplanAttributes - Türanschlag: DIN L
Türöffnung | H2 Ebene +2 | 1213Tür0813690495 | m² | 0 | Zimmer- und Holzbauarbeiten | Türöffnung | 0 | 7.5 | NEW | AllplanAttributes - Türanschlag: DIN R
Türöffnung | H2 Ebene +2 | 1213Tür0813004079 | m² |  | Zimmer- und Holzbauarbeiten | Türöffnung |  | 7.5 | NEW | 1213Wa 0812986403 | REI 90-A1 | AllplanAttributes - Material: WA-STB; Tragendes Bauteil: yes; Brandabschnittsdefinierendes Bauteil: no; Außenliegend: yes; U-Wert: 0; Schallschutzklasse: 0; Codetext: Codetext; Türanschlag: -; Typ: 0; Brennbares Material: no; Brandverhalten: 0; Brandschutzklasse: A; Ortscode_Geschoßbezeichnung: E02; Pset_OpeningElementCommon - Reference: Codetext
Türöffnung | H2 Ebene +2 | 1213Tür0813546973 | m² |  | Zimmer- und Holzbauarbeiten | Türöffnung |  | 7.5 | NEW | 1163Wa 0814107886 | AllplanAttributes - Türanschlag: -; Positionsnummer_Text: U100; Ortscode_Geschoßbezeichnung: E02
2 x Fensteröffnung | H2 Ebene +2 | 1213Fen0813699667 | m² |  | Fensterarbeiten | Fensteröffnung |  | 7.5 |  | 1213Wa 0812971219 | AllplanAttributes - Ortscode_Geschoßbezeichnung: E02
Türöffnung | H2 Ebene +2 | 1213Tür0813004092 | m² |  | Zimmer- und Holzbauarbeiten | Türöffnung |  | 7.5 | NEW | 1213Wa 0812985912 | AllplanAttributes - Codetext: Codetext; Türanschlag: -; Attributset-Objekt: OpeningElement; Pset_OpeningElementCommon - FireExit: no; Reference: Codetext
Türöffnung | H2 Ebene +2 | 1213Tür0813695261 | m² | 0 | Zimmer- und Holzbauarbeiten | Türöffnung | 0 | 7.5 | NEW | AllplanAttributes - Türanschlag: -
Fensteröffnung | H2 Ebene +2 | 1213Fen0813697849 | m² |  | Fensterarbeiten | Fensteröffnung |  | 7.5 |  | 1213Wa 0812971219 | AllplanAttributes - Ortscode_Geschoßbezeichnung: E02
Fensteröffnung | H2 Ebene +2 | 1213Fen0813698218 | m² |  | Fensterarbeiten | Fensteröffnung |  | 7.5 |  | 1213Wa 0812971219 | AllplanAttributes - Ortscode_Geschoßbezeichnung: E02
Fensteröffnung | H2 Ebene +2 | 1213Fen0813698306 | m² |  | Fensterarbeiten | Fensteröffnung |  | 7.5 |  | 1213Wa 0812971219 | AllplanAttributes - Ortscode_Geschoßbezeichnung: E02
Fensteröffnung | H2 Ebene +2 | 1213Fen0813698912 | m² | 0 | Fensterarbeiten | Fensteröffnung | 0 | 7.5 |  | 1213Wa 0812971219 | AllplanAttributes - Ortscode_Geschoßbezeichnung: E02
Fensteröffnung | H2 Ebene +2 | 1213Fen0813698632 | m² |  | Fensterarbeiten | Fensteröffnung |  | 7.5 |  | 1213Wa 0812971219 | AllplanAttributes - Ortscode_Geschoßbezeichnung: E02
Fensteröffnung | H2 Ebene +2 | 1213Fen0813698661 | m² |  | Fensterarbeiten | Fensteröffnung |  | 7.5 |  | 1213Wa 0812971219 | AllplanAttributes - Ortscode_Geschoßbezeichnung: E02
2 x Fensteröffnung | H2 Ebene +2 | 1213Fen0813699727 | m² |  | Fensterarbeiten | Fensteröffnung |  | 7.5 |  | 1213Wa 0812971219 | AllplanAttributes - Ortscode_Geschoßbezeichnung: E02
Fensteröffnung | H2 Ebene +2 | 1213Fen0813699753 | m² |  | Fensterarbeiten | Fensteröffnung |  | 7.5 |  | 1213Wa 0812971219 | AllplanAttributes - Ortscode_Geschoßbezeichnung: E02
Türöffnung | H2 Ebene +2 | 1213Tür0813012820 | m² |  | Zimmer- und Holzbauarbeiten | Türöffnung |  | 7.5 | NEW | 1213Wa 0812986025 | AllplanAttributes - Türanschlag: -; Ortscode_Geschoßbezeichnung: E02
Türöffnung | H2 Ebene +2 | 1213Tür0813004114 | m² |  | Zimmer- und Holzbauarbeiten | Türöffnung |  | 7.5 |  | 1213Wa 0812986078 | AllplanAttributes - Codetext: Codetext; Türanschlag: -; Ortscode_Geschoßbezeichnung: E02; Pset_OpeningElementCommon - FireExit: no; Reference: Codetext
Türöffnung | H2 Ebene +2 | 1213Tür0813004116 | m² |  | Zimmer- und Holzbauarbeiten | Türöffnung |  | 7.5 | NEW | 1213Wa 0812986054 | AllplanAttributes - Türanschlag: -; Ortscode_Geschoßbezeichnung: E02
Türöffnung | H2 Ebene +2 | 1213Tür0813005418 | m² |  | Zimmer- und Holzbauarbeiten | Türöffnung |  | 7.5 | NEW | 1213Wa 0812986461 | REI 90-A1 | AllplanAttributes - Material: WA-STB; Tragendes Bauteil: yes; Brandabschnittsdefinierendes Bauteil: no; Außenliegend: yes; U-Wert: 0; Schallschutzklasse: 0; Codetext: Codetext; Türanschlag: -; Typ: 0; Brennbares Material: no; Brandverhalten: 0; Brandschutzklasse: A; Ortscode_Geschoßbezeichnung: E02; Pset_OpeningElementCommon - Reference: Codetext
Wandnische | H2 Ebene +2 | 1213Wni0813567994 | m² | 0 | Zimmer- und Holzbauarbeiten | Wandnische | 0 | 7.5 | NEW | AllplanAttributes - Ortscode_Geschoßbezeichnung: E02
Wandnische | H2 Ebene +2 | 1213Wni0813705767 | m² | 0 | Zimmer- und Holzbauarbeiten | Wandnische | 0 | 7.5 | NEW | AllplanAttributes - Ortscode_Geschoßbezeichnung: E02
Türöffnung | H2 Ebene +2 | 1213Tür0813004493 | m² | 0 | Trockenbauarbeiten | Türöffnung | 0 | 7.5 | NEW | 1213Wa 0812986166 | AllplanAttributes - Codetext: Codetext; Türanschlag: -; Attributset-Objekt: OpeningElement; ash T_Schallschutz: 37 dB; Ortscode_Geschoßbezeichnung: E02; Pset_OpeningElementCommon - FireExit: no; Reference: Codetext
Türöffnung | H2 Ebene +2 | 1213Tür0813545628 | m² |  | Zimmer- und Holzbauarbeiten | Türöffnung |  | 7.5 | NEW | 1163Wa 0814107886 | AllplanAttributes - Türanschlag: -; Positionsnummer_Text: U100; Ortscode_Geschoßbezeichnung: E02
Türöffnung | H2 Ebene +2 | 1213Tür0813005412 | m² |  | Zimmer- und Holzbauarbeiten | Türöffnung |  | 7.5 | NEW | 1213Wa 0812986412 | - | AllplanAttributes - Codetext: Codetext; Türanschlag: DIN R; Attributset-Objekt: OpeningElement; Rauchschutz: no; Selbstschließend: no; ash T_Unterschnitt: -; ash T_Zulage Schachttür: no; ash T_Dichtschließend: yes; ash T_Zarge_Typ: U; ash T_Erforderl. Durchgangsbreite: 0 m; ash T_Türblatt sichtbar 2D: ja; ash T_Feststellanlage (FSA): -; ash T_nicht abschließbar: no; ash T_Blatt_Oberfläche: -; ash T_Erford. Durgangshöhe: 0 m; ash T_Blatt_Material: -; ash T_Schallschutz: -; ash T_Zarge_Material: S; Ortscode_Geschoßbezeichnung: E02; Pset_OpeningElementCommon - FireExit: no; Reference: Codetext
Türöffnung | H2 Ebene +2 | 1213Tür0813206891 | m² | 0 | Zimmer- und Holzbauarbeiten | Türöffnung | 0 | 7.5 | NEW | AllplanAttributes - Türanschlag: DIN R; Ortscode_Geschoßbezeichnung: E02
Türöffnung | H2 Ebene +2 | 1213Tür0813005320 | m² |  | Zimmer- und Holzbauarbeiten | Türöffnung |  | 7.5 | NEW | 1213Wa 0812985898 | AllplanAttributes - Codetext: Codetext; Türanschlag: DIN R; Attributset-Objekt: OpeningElement; Ortscode_Geschoßbezeichnung: E02; Pset_OpeningElementCommon - FireExit: no; Reference: Codetext
Türöffnung | H2 Ebene +2 | 1213Tür0813005326 | m² |  | Zimmer- und Holzbauarbeiten | Türöffnung |  | 7.5 | NEW | 1213Wa 0812985898 | AllplanAttributes - Codetext: Codetext; Türanschlag: DIN R; Attributset-Objekt: OpeningElement; Ortscode_Geschoßbezeichnung: E02; Pset_OpeningElementCommon - FireExit: no; Reference: Codetext
Türöffnung | H2 Ebene +2 | 1213Tür0813192833 | m² | 0 | Zimmer- und Holzbauarbeiten | Türöffnung | 0 | 7.5 | NEW | 1213Wa 0813192706 | AllplanAttributes - Türanschlag: DIN R; Ortscode_Geschoßbezeichnung: E02
Türöffnung | H2 Ebene +2 | 1213Tür0813192727 | m² | 0 | Zimmer- und Holzbauarbeiten | Türöffnung | 0 | 7.5 | NEW | 1213Wa 0813192706 | AllplanAttributes - Türanschlag: DIN R; Ortscode_Geschoßbezeichnung: E02
Türöffnung | H2 Ebene +2 | 1213Tür0813457903 | m² |  | Zimmer- und Holzbauarbeiten | Türöffnung |  | 7.5 |  | 1213Wa 0812986083 | AllplanAttributes - Codetext: Codetext; Türanschlag: -; Ortscode_Geschoßbezeichnung: E02; Pset_OpeningElementCommon - FireExit: no; Reference: Codetext
Türöffnung | H2 Ebene +2 | 1213Tür0813723094 | m² |  | Zimmer- und Holzbauarbeiten | Türöffnung |  | 7.5 | NEW | 1213Wa 0812985903 | AllplanAttributes - Codetext: Codetext; Türanschlag: DIN R; Attributset-Objekt: OpeningElement; Ortscode_Geschoßbezeichnung: E02; Pset_OpeningElementCommon - FireExit: no; Reference: Codetext
Türöffnung | H2 Ebene +2 | 1213Tür0813723097 | m² | 0 | Zimmer- und Holzbauarbeiten | Türöffnung | 0 | 7.5 | NEW | 1213Wa 0813100280 | AllplanAttributes - Türanschlag: DIN R; Ortscode_Geschoßbezeichnung: E02
Türöffnung | H2 Ebene +2 | 1213Tür0813723099 | m² | 0 | Zimmer- und Holzbauarbeiten | Türöffnung | 0 | 7.5 | NEW | AllplanAttributes - Türanschlag: DIN R; Ortscode_Geschoßbezeichnung: E02
Türöffnung | H2 Ebene +2 | 1213Tür0813004120 | m² |  | Trockenbauarbeiten | Türöffnung |  | 7.5 | NEW | 1213Wa 0812986013 | AllplanAttributes - Türanschlag: -; Ortscode_Geschoßbezeichnung: E02
Türöffnung | H2 Ebene +2 | 1213Tür0813137478 | m² |  | Trockenbauarbeiten | Türöffnung |  | 7.5 | NEW | 1213Wa 0813137593 | AllplanAttributes - Türanschlag: -; Ortscode_Geschoßbezeichnung: E02
Türöffnung | H2 Ebene +2 | 1213Tür0813004482 | m² |  | Zimmer- und Holzbauarbeiten | Türöffnung |  | 7.5 | NEW | 1213Wa 0812986275 | AllplanAttributes - Codetext: Codetext; Türanschlag: DIN R; Attributset-Objekt: OpeningElement; Ortscode_Geschoßbezeichnung: E02; Pset_OpeningElementCommon - FireExit: no; Reference: Codetext
Türöffnung | H2 Ebene +2 | 1213Tür0813085105 | m² | 0 | Zimmer- und Holzbauarbeiten | Türöffnung | 0 | 7.5 | NEW | 1213Wa 0813085084 | AllplanAttributes - Türanschlag: DIN R; Ortscode_Geschoßbezeichnung: E02
Türöffnung | H2 Ebene +2 | 1213Tür0813097632 | m² | 0 | Zimmer- und Holzbauarbeiten | Türöffnung | 0 | 7.5 | NEW | 1213Wa 0813097591 | AllplanAttributes - Türanschlag: DIN R; Ortscode_Geschoßbezeichnung: E02
Türöffnung | H2 Ebene +2 | 1213Tür0813167259 | m² |  | Trockenbauarbeiten | Türöffnung |  | 7.5 | NEW | 1213Wa 0813167303 | AllplanAttributes - Türanschlag: -; Ortscode_Geschoßbezeichnung: E02
Türöffnung | H2 Ebene +2 | 1213Tür0813004138 | m² |  | Trockenbauarbeiten | Türöffnung |  | 7.5 | NEW | 1213Wa 0812985975 | AllplanAttributes - Codetext: Codetext; Türanschlag: DIN R; Attributset-Objekt: OpeningElement; Ortscode_Geschoßbezeichnung: E02; Pset_OpeningElementCommon - FireExit: no; Reference: Codetext
Türöffnung | H2 Ebene +2 | 1213Tür0813196726 | m² | 0 | Trockenbauarbeiten | Türöffnung | 0 | 7.5 | NEW | 1213Wa 0813196706 | AllplanAttributes - Türanschlag: DIN R; Ortscode_Geschoßbezeichnung: E02
Türöffnung | H2 Ebene +2 | 1213Tür0813503799 | m² | 0 | Zimmer- und Holzbauarbeiten | Türöffnung | 0 | 7.5 | NEW | 1113Wa 0812447364 | E 60 | AllplanAttributes - Türanschlag: -; Text1: 15b; Positionsnummer_Text: S68; Ortscode_Geschoßbezeichnung: E02
Türöffnung | H2 Ebene +2 | 1213Tür0813503507 | m² | 0 | Zimmer- und Holzbauarbeiten | Türöffnung | 0 | 7.5 | NEW | 1113Wa 0812447364 | E 60 | AllplanAttributes - Türanschlag: -; Text1: 15b; Positionsnummer_Text: S68; Ortscode_Geschoßbezeichnung: E02
Türöffnung | H2 Ebene +2 | 1213Tür0813005137 | m² |  | Trockenbauarbeiten | Türöffnung |  | 7.5 | NEW | 1213Wa 0812986381 | EI2 30 | AllplanAttributes - Codetext: Codetext; Türanschlag: DIN R; Attributset-Objekt: OpeningElement; Rauchschutz: yes; Selbstschließend: yes; ash T_Zulage Schachttür: no; ash T_Dichtschließend: no; ash T_Feststellanlage (FSA): -; ash T_nicht abschließbar: no; Ortscode_Geschoßbezeichnung: E02; Pset_OpeningElementCommon - FireExit: no; Reference: Codetext
Türöffnung | H2 Ebene +2 | 1213Tür0813503798 | m² | -170 | Zimmer- und Holzbauarbeiten | Türöffnung | 0 | 7.5 | NEW | 1113Wa 0812843889 | AllplanAttributes - Türanschlag: -; Positionsnummer_Text: S68; Ortscode_Geschoßbezeichnung: E02
Türöffnung | H2 Ebene +2 | 1213Tür0813503506 | m² | -170 | Zimmer- und Holzbauarbeiten | Türöffnung | 0 | 7.5 | NEW | 1113Wa 0812843889 | AllplanAttributes - Türanschlag: -; Positionsnummer_Text: S68; Ortscode_Geschoßbezeichnung: E02
Türöffnung | H2 Ebene +2 | 1213Tür0813005143 | m² | 0 | Trockenbauarbeiten | Türöffnung | 0 | 7.5 | NEW | 1213Wa 0812986375 | AllplanAttributes - Türanschlag: DIN R; ash T_Feststellanlage (FSA): -; Ortscode_Geschoßbezeichnung: E02
Türöffnung | H2 Ebene +2 | 1213Tür0813004223 | m² |  | Trockenbauarbeiten | Türöffnung |  | 7.5 | NEW | 1213Wa 0812986171 | AllplanAttributes - Bezeichnung: Türöffnung; Codetext: Codetext; Türanschlag: -; Attributset-Objekt: OpeningElement; Ortscode_Geschoßbezeichnung: E02; Pset_OpeningElementCommon - FireExit: no; Reference: Codetext
Türöffnung | H2 Ebene +2 | 1213Tür0813746526 | m² | 0 | Trockenbauarbeiten | Türöffnung | 0 | 7.5 | NEW | 1213Wa 0812986139 | AllplanAttributes - Codetext: Codetext; Türanschlag: -; Attributset-Objekt: OpeningElement; Pset_OpeningElementCommon - FireExit: no; Reference: Codetext
Türöffnung | H2 Ebene +2 | 1213Tür0813751186 | m² |  | Zimmer- und Holzbauarbeiten | Türöffnung |  | 7.5 | NEW | 1213Wa 0812986393 | AllplanAttributes - Codetext: Codetext; Türanschlag: DIN L; Attributset-Objekt: OpeningElement; Pset_OpeningElementCommon - FireExit: no; Reference: Codetext
Türöffnung | H2 Ebene +2 | 1213Tür0813751192 | m² | 0 | Zimmer- und Holzbauarbeiten | Türöffnung | 0 | 7.5 | NEW | 1213Wa 0813191123 | AllplanAttributes - Türanschlag: DIN L
Türöffnung | H2 Ebene +2 | 1213Tür0813751291 | m² | 0 | Zimmer- und Holzbauarbeiten | Türöffnung | 0 |  | NEW | AllplanAttributes - Türanschlag: DIN L
Bodendurchbruch | H2 Ebene +2 |  |  |  |  |  |  |  | NEW | Pset_OpeningElementCommon - FireExit: no; AllplanAttributes - Object Layer Attributes #1, Gewerk: Betonarbeiten; Object Layer Attributes #1, Allright_Bauteil_ID: 1214Ddu0813473004; Object Layer Attributes #1, Abrechnungsart: m²; Object Layer Attributes #1, Objektname: Bodendurchbruch; Object Layer Attributes #1, Attributset-Objekt: OpeningElement
Bodendurchbruch | H2 Ebene +2 |  |  |  |  |  |  |  | NEW | Pset_OpeningElementCommon - FireExit: no; AllplanAttributes - Object Layer Attributes #1, Gewerk: Betonarbeiten; Object Layer Attributes #1, Allright_Bauteil_ID: 1214Ddu0813475174; Object Layer Attributes #1, Abrechnungsart: m²; Object Layer Attributes #1, Objektname: Bodendurchbruch; Object Layer Attributes #1, Attributset-Objekt: OpeningElement
Bodendurchbruch | H2 Ebene +2 |  |  |  |  |  |  |  | NEW | Pset_OpeningElementCommon - FireExit: no; AllplanAttributes - Object Layer Attributes #1, Gewerk: Betonarbeiten; Object Layer Attributes #1, Allright_Bauteil_ID: 1214Ddu0813473071; Object Layer Attributes #1, Abrechnungsart: m²; Object Layer Attributes #1, Objektname: Bodendurchbruch; Object Layer Attributes #1, Attributset-Objekt: OpeningElement
Deckendurchbruch | H2 Ebene +2 |  |  |  |  |  |  |  | NEW | Pset_OpeningElementCommon - FireExit: no; AllplanAttributes - Object Layer Attributes #1, Gewerk: Betonarbeiten; Object Layer Attributes #1, Allright_Bauteil_ID: 1214Ddu0813471148; Object Layer Attributes #1, Abrechnungsart: m²; Object Layer Attributes #1, Objektname: Bodendurchbruch; Object Layer Attributes #1, Attributset-Objekt: OpeningElement; Object Layer Attributes #1, Feuerwiderstandsklasse: 0; Object Layer Attributes #1, U-Wert: 0.9; Object Layer Attributes #1, Schallschutzklasse: 32; Object Layer Attributes #1, Sicherheitsklasse: -; Object Layer Attributes #1, Sonnenschutztyp: Movable; Object Layer Attributes #1, g-Wert: 0,51
Deckendurchbruch | H2 Ebene +2 |  |  |  |  |  |  |  | NEW | Pset_OpeningElementCommon - FireExit: no; AllplanAttributes - Object Layer Attributes #1, Gewerk: Betonarbeiten; Object Layer Attributes #1, Allright_Bauteil_ID: 1214Ddu0813471113; Object Layer Attributes #1, Abrechnungsart: m²; Object Layer Attributes #1, Objektname: Bodendurchbruch; Object Layer Attributes #1, Attributset-Objekt: OpeningElement; Object Layer Attributes #1, Feuerwiderstandsklasse: 0; Object Layer Attributes #1, U-Wert: 0.9; Object Layer Attributes #1, Schallschutzklasse: 32; Object Layer Attributes #1, Sicherheitsklasse: -; Object Layer Attributes #1, Sonnenschutztyp: Movable; Object Layer Attributes #1, g-Wert: 0,51
Deckendurchbruch | H2 Ebene +2 |  |  |  |  |  |  |  | NEW | Pset_OpeningElementCommon - FireExit: no; AllplanAttributes - Object Layer Attributes #1, Gewerk: Betonarbeiten; Object Layer Attributes #1, Allright_Bauteil_ID: 1214Ddu0813475082; Object Layer Attributes #1, Abrechnungsart: m²; Object Layer Attributes #1, Objektname: Bodendurchbruch; Object Layer Attributes #1, Attributset-Objekt: OpeningElement; Object Layer Attributes #1, Feuerwiderstandsklasse: 0; Object Layer Attributes #1, U-Wert: 0.9; Object Layer Attributes #1, Schallschutzklasse: 32; Object Layer Attributes #1, Sicherheitsklasse: -; Object Layer Attributes #1, Sonnenschutztyp: Movable; Object Layer Attributes #1, g-Wert: 0,51
Deckendurchbruch | H2 Ebene +2 |  |  |  |  |  |  |  | NEW | Pset_OpeningElementCommon - FireExit: no; AllplanAttributes - Object Layer Attributes #1, Gewerk: Betonarbeiten; Object Layer Attributes #1, Allright_Bauteil_ID: 1214Ddu0813475096; Object Layer Attributes #1, Abrechnungsart: m²; Object Layer Attributes #1, Objektname: Bodendurchbruch; Object Layer Attributes #1, Attributset-Objekt: OpeningElement; Object Layer Attributes #1, Feuerwiderstandsklasse: 0; Object Layer Attributes #1, U-Wert: 0.9; Object Layer Attributes #1, Schallschutzklasse: 32; Object Layer Attributes #1, Sicherheitsklasse: -; Object Layer Attributes #1, Sonnenschutztyp: Movable; Object Layer Attributes #1, g-Wert: 0,51
Deckendurchbruch | H2 Ebene +2 |  |  |  |  |  |  |  | NEW | Pset_OpeningElementCommon - FireExit: no; AllplanAttributes - Object Layer Attributes #1, Gewerk: Betonarbeiten; Object Layer Attributes #1, Allright_Bauteil_ID: 1214Ddu0000008087; Object Layer Attributes #1, Abrechnungsart: m²; Object Layer Attributes #1, Objektname: Bodendurchbruch; Object Layer Attributes #1, Attributset-Objekt: OpeningElement; Object Layer Attributes #1, Feuerwiderstandsklasse: 0; Object Layer Attributes #1, U-Wert: 0.9; Object Layer Attributes #1, Schallschutzklasse: 32; Object Layer Attributes #1, Sicherheitsklasse: -; Object Layer Attributes #1, Sonnenschutztyp: Movable; Object Layer Attributes #1, g-Wert: 0,51
Deckendurchbruch | H2 Ebene +2 |  |  |  |  |  |  |  | NEW | Pset_OpeningElementCommon - FireExit: no; AllplanAttributes - Object Layer Attributes #1, Gewerk: Betonarbeiten; Object Layer Attributes #1, Allright_Bauteil_ID: 1214Ddu0813471085; Object Layer Attributes #1, Abrechnungsart: m²; Object Layer Attributes #1, Objektname: Bodendurchbruch; Object Layer Attributes #1, Attributset-Objekt: OpeningElement; Object Layer Attributes #1, Feuerwiderstandsklasse: 0; Object Layer Attributes #1, U-Wert: 0.9; Object Layer Attributes #1, Schallschutzklasse: 32; Object Layer Attributes #1, Sicherheitsklasse: -; Object Layer Attributes #1, Sonnenschutztyp: Movable; Object Layer Attributes #1, g-Wert: 0,51
Türöffnung | H2 Ebene +1 | 1155Tür0813754076 | m² |  | Trockenbauarbeiten | Türöffnung |  | 3.75 | NEW | 1105Wa 0811567313 | 0 | RC 1 | 0,51 | AllplanAttributes - Codetext: Codetext; Türanschlag: DIN L; Positionsnummer_Text: U23; Pset_OpeningElementCommon - FireExit: no; Reference: Codetext
Türöffnung | H2 Ebene +1 | 1155Tür0813754080 | m³ | 0 | Trockenbauarbeiten | Türöffnung | 0 | 3.75 | NEW | 1105Wa 0811567314 | 0 | RC 1 | 0,51 | AllplanAttributes - Türanschlag: DIN L; Positionsnummer_Text: U23
Türöffnung | H2 Ebene +1 | 1155Tür0813754082 | m³ | 0 | Trockenbauarbeiten | Türöffnung | 0 | 3.75 | NEW | 1105Wa 0811567315 | 0 | RC 1 | 0,51 | AllplanAttributes - Türanschlag: DIN L; Positionsnummer_Text: U23
Türöffnung | H2 Ebene +1 | 1155Tür0813754070 | m² | 0 | Trockenbauarbeiten | Türöffnung | 0 | 3.75 | NEW | 1105Wa 0811567316 | 0 | RC 1 | 0,51 | AllplanAttributes - Türanschlag: DIN L; Positionsnummer_Text: U23
Türöffnung | H2 Ebene +1 | 1155Tür0813754078 | m² | 0 | Trockenbauarbeiten | Türöffnung | 0 | 3.75 | NEW | 1105Wa 0811567317 | 0 | RC 1 | 0,51 | AllplanAttributes - Türanschlag: DIN L; Positionsnummer_Text: U23
Türöffnung | H2 Ebene +1 | 1155Tür0813754072 | m² | 0 | Trockenbauarbeiten | Türöffnung | 0 | 3.75 | NEW | 1105Wa 0811567318 | 0 | RC 1 | 0,51 | AllplanAttributes - Türanschlag: DIN L; Positionsnummer_Text: U23
Türöffnung | H2 Ebene +1 | 1155Tür0813754074 | m² | 0 | Trockenbauarbeiten | Türöffnung | 0 | 3.75 | NEW | 1105Wa 0811567319 | 0 | RC 1 | 0,51 | AllplanAttributes - Türanschlag: DIN L; Positionsnummer_Text: U23
Fensteröffnung | H2 Ebene +1 | 1155Fen0000005554 | m² | 0 | Fensterarbeiten | Fensteröffnung | 0 | 3.75 |  | 1155Wa 0000003844 | 0 | - | 0,51 | AllplanAttributes - U-Wert: 0.9; Schallschutzklasse: 32; Sonnenschutztyp: Movable
Fensteröffnung | H2 Ebene +1 | 1155Fen0000005545 | m² | 0 | Fensterarbeiten | Fensteröffnung | 0 | 3.75 |  | 1155Wa 0000003844 | 0 | - | 0,51 | AllplanAttributes - U-Wert: 0.9; Schallschutzklasse: 32; Sonnenschutztyp: Movable
Fensteröffnung | H2 Ebene +1 | 1155Fen0000005551 | m² | 0 | Fensterarbeiten | Fensteröffnung | 0 | 3.75 |  | 1155Wa 0000003844 | 0 | - | 0,51 | AllplanAttributes - U-Wert: 0.9; Schallschutzklasse: 32; Sonnenschutztyp: Movable
Fensteröffnung | H2 Ebene +1 | 1155Fen0000005539 | m² | 0 | Fensterarbeiten | Fensteröffnung | 0 | 3.75 |  | 1155Wa 0000003844 | 0 | - | 0,51 | AllplanAttributes - U-Wert: 0.9; Schallschutzklasse: 32; Sonnenschutztyp: Movable
Fensteröffnung | H2 Ebene +1 | 1155Fen0000005536 | m² | 0 | Fensterarbeiten | Fensteröffnung | 0 | 3.75 |  | 1155Wa 0000003844 | 0 | - | 0,51 | AllplanAttributes - U-Wert: 0.9; Schallschutzklasse: 32; Sonnenschutztyp: Movable
Fensteröffnung | H2 Ebene +1 | 1155Fen0000005542 | m² | 0 | Fensterarbeiten | Fensteröffnung | 0 | 3.75 |  | 1155Wa 0000003844 | 0 | - | 0,51 | AllplanAttributes - U-Wert: 0.9; Schallschutzklasse: 32; Sonnenschutztyp: Movable
Fensteröffnung | H2 Ebene +1 | 1155Fen0000003375 | m³ | 0 | Fensterarbeiten | Fensteröffnung | 0 | 3.75 |  | 1155Wa 0000003834 | 0 | - | 0,51 | AllplanAttributes - U-Wert: 0.9; Schallschutzklasse: 32; Sonnenschutztyp: Movable
Fensteröffnung | H2 Ebene +1 | 1155Fen0000003363 | m³ | 0 | Fensterarbeiten | Fensteröffnung | 0 | 3.75 |  | 1155Wa 0000003834 | 0 | - | 0,51 | AllplanAttributes - U-Wert: 0.9; Schallschutzklasse: 32; Sonnenschutztyp: Movable
Fensteröffnung | H2 Ebene +1 | 1155Fen0000003371 | m³ | 0 | Fensterarbeiten | Fensteröffnung | 0 | 3.75 |  | 1155Wa 0000003834 | 0 | - | 0,51 | AllplanAttributes - U-Wert: 0.9; Schallschutzklasse: 32; Sonnenschutztyp: Movable
Fensteröffnung | H2 Ebene +1 | 1155Fen0000003355 | m³ | 0 | Fensterarbeiten | Fensteröffnung | 0 | 3.75 |  | 1155Wa 0000003834 | 0 | - | 0,51 | AllplanAttributes - U-Wert: 0.9; Schallschutzklasse: 32; Sonnenschutztyp: Movable
Fensteröffnung | H2 Ebene +1 | 1155Fen0000003351 | m³ | 0 | Fensterarbeiten | Fensteröffnung | 0 | 3.75 |  | 1155Wa 0000003834 | 0 | - | 0,51 | AllplanAttributes - U-Wert: 0.9; Schallschutzklasse: 32; Sonnenschutztyp: Movable
Fensteröffnung | H2 Ebene +1 | 1155Fen0000003359 | m³ | 0 | Fensterarbeiten | Fensteröffnung | 0 | 3.75 |  | 1155Wa 0000003834 | 0 | - | 0,51 | AllplanAttributes - U-Wert: 0.9; Schallschutzklasse: 32; Sonnenschutztyp: Movable
Fensteröffnung | H2 Ebene +1 | 1155Fen0000003377 | m³ | 0 | Fensterarbeiten | Fensteröffnung | 0 | 3.75 |  | 1155Wa 0000003824 | 0 | - | 0,51 | AllplanAttributes - U-Wert: 0.9; Schallschutzklasse: 32; Sonnenschutztyp: Movable
Fensteröffnung | H2 Ebene +1 | 1155Fen0000003365 | m³ | 0 | Fensterarbeiten | Fensteröffnung | 0 | 3.75 |  | 1155Wa 0000003824 | 0 | - | 0,51 | AllplanAttributes - U-Wert: 0.9; Schallschutzklasse: 32; Sonnenschutztyp: Movable
Fensteröffnung | H2 Ebene +1 | 1155Fen0000003373 | m³ | 0 | Fensterarbeiten | Fensteröffnung | 0 | 3.75 |  | 1155Wa 0000003824 | 0 | - | 0,51 | AllplanAttributes - U-Wert: 0.9; Schallschutzklasse: 32; Sonnenschutztyp: Movable
Fensteröffnung | H2 Ebene +1 | 1155Fen0000003357 | m³ | 0 | Fensterarbeiten | Fensteröffnung | 0 | 3.75 |  | 1155Wa 0000003824 | 0 | - | 0,51 | AllplanAttributes - U-Wert: 0.9; Schallschutzklasse: 32; Sonnenschutztyp: Movable
Fensteröffnung | H2 Ebene +1 | 1155Fen0000003353 | m³ | 0 | Fensterarbeiten | Fensteröffnung | 0 | 3.75 |  | 1155Wa 0000003824 | 0 | - | 0,51 | AllplanAttributes - U-Wert: 0.9; Schallschutzklasse: 32; Sonnenschutztyp: Movable
Fensteröffnung | H2 Ebene +1 | 1155Fen0000003361 | m³ | 0 | Fensterarbeiten | Fensteröffnung | 0 | 3.75 |  | 1155Wa 0000003824 | 0 | - | 0,51 | AllplanAttributes - U-Wert: 0.9; Schallschutzklasse: 32; Sonnenschutztyp: Movable
Fensteröffnung | H2 Ebene +1 | 1155Fen0000003343 | m² | 0 | Fensterarbeiten | Fensteröffnung | 0 | 3.75 |  | 1155Wa 0000003814 | 0 | - | 0,51 | AllplanAttributes - U-Wert: 0.9; Schallschutzklasse: 32; Sonnenschutztyp: Movable
Fensteröffnung | H2 Ebene +1 | 1155Fen0000003319 | m² | 0 | Fensterarbeiten | Fensteröffnung | 0 | 3.75 |  | 1155Wa 0000003814 | 0 | - | 0,51 | AllplanAttributes - U-Wert: 0.9; Schallschutzklasse: 32; Sonnenschutztyp: Movable
Fensteröffnung | H2 Ebene +1 | 1155Fen0000003335 | m² | 0 | Fensterarbeiten | Fensteröffnung | 0 | 3.75 |  | 1155Wa 0000003814 | 0 | - | 0,51 | AllplanAttributes - U-Wert: 0.9; Schallschutzklasse: 32; Sonnenschutztyp: Movable
Fensteröffnung | H2 Ebene +1 | 1155Fen0000003303 | m² | 0 | Fensterarbeiten | Fensteröffnung | 0 | 3.75 |  | 1155Wa 0000003814 | 0 | - | 0,51 | AllplanAttributes - U-Wert: 0.9; Schallschutzklasse: 32; Sonnenschutztyp: Movable
Fensteröffnung | H2 Ebene +1 | 1155Fen0000003295 | m² | 0 | Fensterarbeiten | Fensteröffnung | 0 | 3.75 |  | 1155Wa 0000003814 | 0 | - | 0,51 | AllplanAttributes - U-Wert: 0.9; Schallschutzklasse: 32; Sonnenschutztyp: Movable
Fensteröffnung | H2 Ebene +1 | 1155Fen0000003311 | m² | 0 | Fensterarbeiten | Fensteröffnung | 0 | 3.75 |  | 1155Wa 0000003814 | 0 | - | 0,51 | AllplanAttributes - U-Wert: 0.9; Schallschutzklasse: 32; Sonnenschutztyp: Movable
Fensteröffnung | H2 Ebene +1 | 1155Fen0000003345 | m² | 0 | Fensterarbeiten | Fensteröffnung | 0 | 3.75 | NEW | 1155Wa 0000003804 | 0 | - | 0,51 | AllplanAttributes - U-Wert: 0.9; Schallschutzklasse: 32; Sonnenschutztyp: Movable
Fensteröffnung | H2 Ebene +1 | 1155Fen0000003321 | m² | 0 | Fensterarbeiten | Fensteröffnung | 0 | 3.75 | NEW | 1155Wa 0000003804 | 0 | - | 0,51 | AllplanAttributes - U-Wert: 0.9; Schallschutzklasse: 32; Sonnenschutztyp: Movable
Fensteröffnung | H2 Ebene +1 | 1155Fen0000003337 | m² | 0 | Fensterarbeiten | Fensteröffnung | 0 | 3.75 | NEW | 1155Wa 0000003804 | 0 | - | 0,51 | AllplanAttributes - U-Wert: 0.9; Schallschutzklasse: 32; Sonnenschutztyp: Movable
Fensteröffnung | H2 Ebene +1 | 1155Fen0000003305 | m² | 0 | Fensterarbeiten | Fensteröffnung | 0 | 3.75 | NEW | 1155Wa 0000003804 | 0 | - | 0,51 | AllplanAttributes - U-Wert: 0.9; Schallschutzklasse: 32; Sonnenschutztyp: Movable
Fensteröffnung | H2 Ebene +1 | 1155Fen0000003297 | m² | 0 | Fensterarbeiten | Fensteröffnung | 0 | 3.75 | NEW | 1155Wa 0000003804 | 0 | - | 0,51 | AllplanAttributes - U-Wert: 0.9; Schallschutzklasse: 32; Sonnenschutztyp: Movable
Fensteröffnung | H2 Ebene +1 | 1155Fen0000003313 | m² | 0 | Fensterarbeiten | Fensteröffnung | 0 | 3.75 | NEW | 1155Wa 0000003804 | 0 | - | 0,51 | AllplanAttributes - U-Wert: 0.9; Schallschutzklasse: 32; Sonnenschutztyp: Movable
Fensteröffnung | H2 Ebene +1 | 1155Fen0000003347 | m² | 0 | Fensterarbeiten | Fensteröffnung | 0 | 3.75 | NEW | 1155Wa 0000003794 | 0 | - | 0,51 | AllplanAttributes - U-Wert: 0.9; Schallschutzklasse: 32; Sonnenschutztyp: Movable
Fensteröffnung | H2 Ebene +1 | 1155Fen0000003323 | m² | 0 | Fensterarbeiten | Fensteröffnung | 0 | 3.75 | NEW | 1155Wa 0000003794 | 0 | - | 0,51 | AllplanAttributes - U-Wert: 0.9; Schallschutzklasse: 32; Sonnenschutztyp: Movable
Fensteröffnung | H2 Ebene +1 | 1155Fen0000003339 | m² | 0 | Fensterarbeiten | Fensteröffnung | 0 | 3.75 | NEW | 1155Wa 0000003794 | 0 | - | 0,51 | AllplanAttributes - U-Wert: 0.9; Schallschutzklasse: 32; Sonnenschutztyp: Movable
Fensteröffnung | H2 Ebene +1 | 1155Fen0000003307 | m² | 0 | Fensterarbeiten | Fensteröffnung | 0 | 3.75 | NEW | 1155Wa 0000003794 | 0 | - | 0,51 | AllplanAttributes - U-Wert: 0.9; Schallschutzklasse: 32; Sonnenschutztyp: Movable
Fensteröffnung | H2 Ebene +1 | 1155Fen0000003299 | m² | 0 | Fensterarbeiten | Fensteröffnung | 0 | 3.75 | NEW | 1155Wa 0000003794 | 0 | - | 0,51 | AllplanAttributes - U-Wert: 0.9; Schallschutzklasse: 32; Sonnenschutztyp: Movable
Fensteröffnung | H2 Ebene +1 | 1155Fen0000003315 | m² | 0 | Fensterarbeiten | Fensteröffnung | 0 | 3.75 | NEW | 1155Wa 0000003794 | 0 | - | 0,51 | AllplanAttributes - U-Wert: 0.9; Schallschutzklasse: 32; Sonnenschutztyp: Movable
Fensteröffnung | H2 Ebene +1 | 1155Fen0000003349 | m² | 0 | Fensterarbeiten | Fensteröffnung | 0 | 3.75 | NEW | 1155Wa 0000003784 | 0 | - | 0,51 | AllplanAttributes - U-Wert: 0.9; Schallschutzklasse: 32; Sonnenschutztyp: Movable
Fensteröffnung | H2 Ebene +1 | 1155Fen0000003325 | m² | 0 | Fensterarbeiten | Fensteröffnung | 0 | 3.75 | NEW | 1155Wa 0000003784 | 0 | - | 0,51 | AllplanAttributes - U-Wert: 0.9; Schallschutzklasse: 32; Sonnenschutztyp: Movable
Fensteröffnung | H2 Ebene +1 | 1155Fen0000003341 | m² | 0 | Fensterarbeiten | Fensteröffnung | 0 | 3.75 | NEW | 1155Wa 0000003784 | 0 | - | 0,51 | AllplanAttributes - U-Wert: 0.9; Schallschutzklasse: 32; Sonnenschutztyp: Movable
Fensteröffnung | H2 Ebene +1 | 1155Fen0000003309 | m² | 0 | Fensterarbeiten | Fensteröffnung | 0 | 3.75 | NEW | 1155Wa 0000003784 | 0 | - | 0,51 | AllplanAttributes - U-Wert: 0.9; Schallschutzklasse: 32; Sonnenschutztyp: Movable
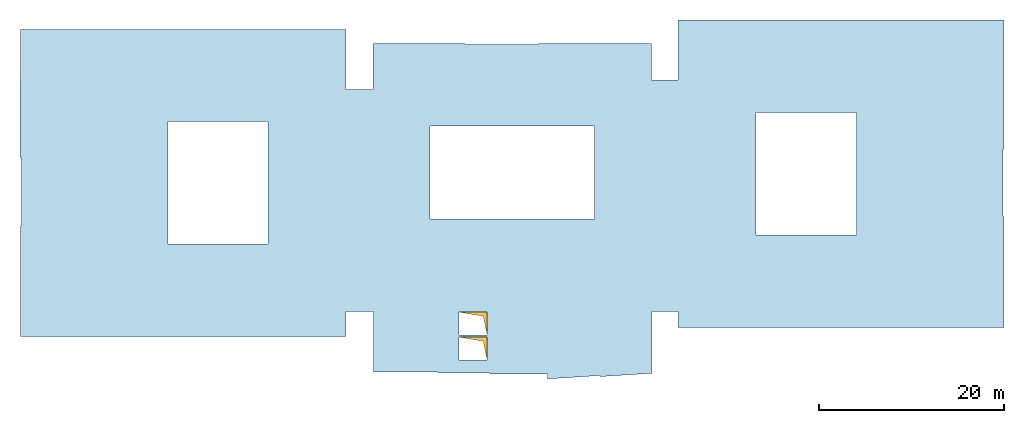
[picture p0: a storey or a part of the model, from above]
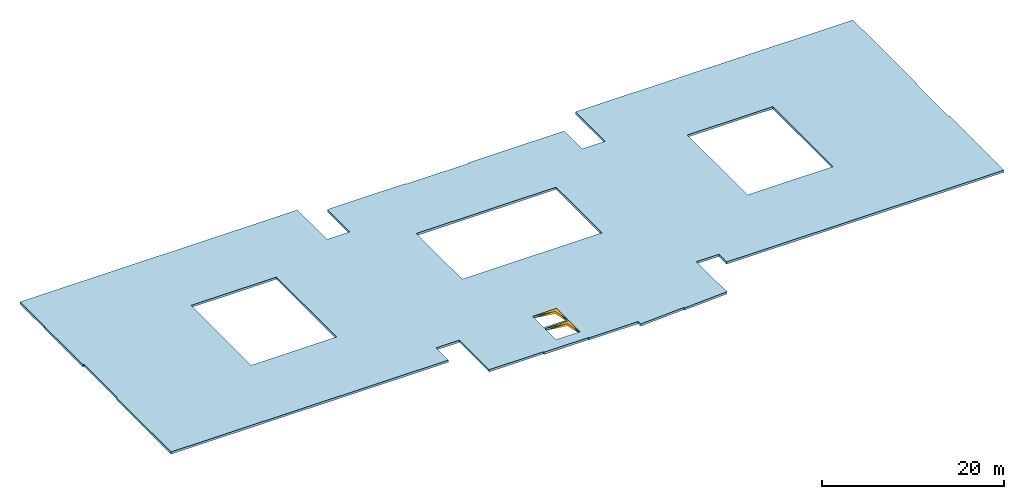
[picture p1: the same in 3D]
Properties of the parts of a building model (IFC4), part 35 of 80

# IfcOpeningElement: Opening (3497)
Name | In | Allright_Bauteil_ID | Abrechnungsart | Versatz_oben | Gewerk | Objektname | Versatz_unten | OKFF | Status | P_ID | AllplanAttributes, Feuerwiderstandsklasse | Sicherheitsklasse | g-Wert
Fensteröffnung | H2 Ebene +1 | 1155Fen0000003301 | m² | 0 | Fensterarbeiten | Fensteröffnung | 0 | 3.75 | NEW | 1155Wa 0000003784 | 0 | - | 0,51 | AllplanAttributes - U-Wert: 0.9; Schallschutzklasse: 32; Sonnenschutztyp: Movable
Fensteröffnung | H2 Ebene +1 | 1155Fen0000003317 | m² | 0 | Fensterarbeiten | Fensteröffnung | 0 | 3.75 | NEW | 1155Wa 0000003784 | 0 | - | 0,51 | AllplanAttributes - U-Wert: 0.9; Schallschutzklasse: 32; Sonnenschutztyp: Movable
Fensteröffnung | H2 Ebene +1 | 1155Fen0000012017 | m² |  | Wärmedämm-Verbundsysteme | Fensteröffnung |  | 3.75 | NEW | 1155Wa 0000001159 | 0 | - | 0,51 | AllplanAttributes - Material: Fensterelement; Tragendes Bauteil: no; Brandabschnittsdefinierendes Bauteil: no; U-Wert: 0.9; Schallschutzklasse: 32; Sonnenschutztyp: Movable
Fensteröffnung | H2 Ebene +1 | 1155Fen0000011966 | m² |  | Wärmedämm-Verbundsysteme | Fensteröffnung |  | 3.75 | NEW | 1155Wa 0000001159 | 0 | - | 0,51 | AllplanAttributes - Material: Fensterelement; Tragendes Bauteil: no; Brandabschnittsdefinierendes Bauteil: no; U-Wert: 0.9; Schallschutzklasse: 32; Sonnenschutztyp: Movable
Fensteröffnung | H2 Ebene +1 | 1155Fen0000012005 | m³ | 0 | Wärmedämm-Verbundsysteme | Fensteröffnung | 0 | 3.75 | NEW | 1155Wa 0000001155 | 0 | - | 0,51 | AllplanAttributes - Material: Fensterelement; Außenliegend: yes; U-Wert: 0.9; Schallschutzklasse: 32; Sonnenschutztyp: Movable
Fensteröffnung | H2 Ebene +1 | 1155Fen0000012020 | m³ | 0 | Wärmedämm-Verbundsysteme | Fensteröffnung | 0 | 3.75 | NEW | 1155Wa 0000001155 | 0 | - | 0,51 | AllplanAttributes - Material: Fensterelement; Außenliegend: yes; U-Wert: 0.9; Schallschutzklasse: 32; Sonnenschutztyp: Movable
Fensteröffnung | H2 Ebene +1 | 1155Fen0000012022 | m³ | 0 | Wärmedämm-Verbundsysteme | Fensteröffnung | 0 | 3.75 | NEW | 1155Wa 0000001135 | 0 | - | 0,51 | AllplanAttributes - U-Wert: 0.9; Schallschutzklasse: 32; Sonnenschutztyp: Movable
Fensteröffnung | H2 Ebene +1 | 1155Fen0000012007 | m³ | 0 | Wärmedämm-Verbundsysteme | Fensteröffnung | 0 | 3.75 | NEW | 1155Wa 0000001135 | 0 | - | 0,51 | AllplanAttributes - U-Wert: 0.9; Schallschutzklasse: 32; Sonnenschutztyp: Movable
Fensteröffnung | H2 Ebene +1 | 1155Fen0000012009 | m² | 0 | Wärmedämm-Verbundsysteme | Fensteröffnung | 0 | 3.75 | NEW | 1155Wa 0000001139 | 0 | - | 0,51 | AllplanAttributes - U-Wert: 0.9; Schallschutzklasse: 32; Sonnenschutztyp: Movable
Fensteröffnung | H2 Ebene +1 | 1155Fen0000012024 | m² | 0 | Wärmedämm-Verbundsysteme | Fensteröffnung | 0 | 3.75 | NEW | 1155Wa 0000001139 | 0 | - | 0,51 | AllplanAttributes - U-Wert: 0.9; Schallschutzklasse: 32; Sonnenschutztyp: Movable
Fensteröffnung | H2 Ebene +1 | 1155Fen0000012011 | m² | 0 | Wärmedämm-Verbundsysteme | Fensteröffnung | 0 | 3.75 | NEW | 1155Wa 0000001143 | 0 | - | 0,51 | AllplanAttributes - U-Wert: 0.9; Schallschutzklasse: 32; Sonnenschutztyp: Movable
Fensteröffnung | H2 Ebene +1 | 1155Fen0000012026 | m² | 0 | Wärmedämm-Verbundsysteme | Fensteröffnung | 0 | 3.75 | NEW | 1155Wa 0000001143 | 0 | - | 0,51 | AllplanAttributes - U-Wert: 0.9; Schallschutzklasse: 32; Sonnenschutztyp: Movable
Fensteröffnung | H2 Ebene +1 | 1155Fen0000012013 | m² | 0 | Wärmedämm-Verbundsysteme | Fensteröffnung | 0 | 3.75 | NEW | 1155Wa 0000001147 | 0 | - | 0,51 | AllplanAttributes - U-Wert: 0.9; Schallschutzklasse: 32; Sonnenschutztyp: Movable
Fensteröffnung | H2 Ebene +1 | 1155Fen0000012028 | m² | 0 | Wärmedämm-Verbundsysteme | Fensteröffnung | 0 | 3.75 | NEW | 1155Wa 0000001147 | 0 | - | 0,51 | AllplanAttributes - U-Wert: 0.9; Schallschutzklasse: 32; Sonnenschutztyp: Movable
Fensteröffnung | H2 Ebene +1 | 1155Fen0000012030 | m² | 0 | Wärmedämm-Verbundsysteme | Fensteröffnung | 0 | 3.75 | NEW | 1155Wa 0000001151 | 0 | - | 0,51 | AllplanAttributes - U-Wert: 0.9; Schallschutzklasse: 32; Sonnenschutztyp: Movable
Fensteröffnung | H2 Ebene +1 | 1155Fen0000012015 | m² | 0 | Wärmedämm-Verbundsysteme | Fensteröffnung | 0 | 3.75 | NEW | 1155Wa 0000001151 | 0 | - | 0,51 | AllplanAttributes - U-Wert: 0.9; Schallschutzklasse: 32; Sonnenschutztyp: Movable
Fensteröffnung | H2 Ebene +1 | 1155Fen0000012047 | m² |  | Wärmedämm-Verbundsysteme | Fensteröffnung |  | 3.75 | NEW | 1155Wa 0000003112 | 0 | - | 0,51 | AllplanAttributes - Material: Fensterelement; Tragendes Bauteil: no; Brandabschnittsdefinierendes Bauteil: no; U-Wert: 0.9; Schallschutzklasse: 32; Sonnenschutztyp: Movable
Fensteröffnung | H2 Ebene +1 | 1155Fen0000012032 | m² |  | Wärmedämm-Verbundsysteme | Fensteröffnung |  | 3.75 | NEW | 1155Wa 0000003112 | 0 | - | 0,51 | AllplanAttributes - Material: Fensterelement; Tragendes Bauteil: no; Brandabschnittsdefinierendes Bauteil: no; U-Wert: 0.9; Schallschutzklasse: 32; Sonnenschutztyp: Movable
Fensteröffnung | H2 Ebene +1 | 1155Fen0000012035 | m³ | 0 | Wärmedämm-Verbundsysteme | Fensteröffnung | 0 | 3.75 | NEW | 1155Wa 0000003108 | 0 | - | 0,51 | AllplanAttributes - Material: Fensterelement; Außenliegend: yes; U-Wert: 0.9; Schallschutzklasse: 32; Sonnenschutztyp: Movable
Fensteröffnung | H2 Ebene +1 | 1155Fen0000012050 | m³ | 0 | Wärmedämm-Verbundsysteme | Fensteröffnung | 0 | 3.75 | NEW | 1155Wa 0000003108 | 0 | - | 0,51 | AllplanAttributes - Material: Fensterelement; Außenliegend: yes; U-Wert: 0.9; Schallschutzklasse: 32; Sonnenschutztyp: Movable
Fensteröffnung | H2 Ebene +1 | 1155Fen0000012037 | m³ | 0 | Wärmedämm-Verbundsysteme | Fensteröffnung | 0 | 3.75 | NEW | 1155Wa 0000003104 | 0 | - | 0,51 | AllplanAttributes - U-Wert: 0.9; Schallschutzklasse: 32; Sonnenschutztyp: Movable
Fensteröffnung | H2 Ebene +1 | 1155Fen0000012052 | m³ | 0 | Wärmedämm-Verbundsysteme | Fensteröffnung | 0 | 3.75 | NEW | 1155Wa 0000003104 | 0 | - | 0,51 | AllplanAttributes - U-Wert: 0.9; Schallschutzklasse: 32; Sonnenschutztyp: Movable
Fensteröffnung | H2 Ebene +1 | 1155Fen0000012054 | m² | 0 | Wärmedämm-Verbundsysteme | Fensteröffnung | 0 | 3.75 | NEW | 1155Wa 0000003100 | 0 | - | 0,51 | AllplanAttributes - U-Wert: 0.9; Schallschutzklasse: 32; Sonnenschutztyp: Movable
Fensteröffnung | H2 Ebene +1 | 1155Fen0000012039 | m² | 0 | Wärmedämm-Verbundsysteme | Fensteröffnung | 0 | 3.75 | NEW | 1155Wa 0000003100 | 0 | - | 0,51 | AllplanAttributes - U-Wert: 0.9; Schallschutzklasse: 32; Sonnenschutztyp: Movable
Fensteröffnung | H2 Ebene +1 | 1155Fen0000012056 | m² | 0 | Wärmedämm-Verbundsysteme | Fensteröffnung | 0 | 3.75 | NEW | 1155Wa 0000003096 | 0 | - | 0,51 | AllplanAttributes - U-Wert: 0.9; Schallschutzklasse: 32; Sonnenschutztyp: Movable
Fensteröffnung | H2 Ebene +1 | 1155Fen0000012041 | m² | 0 | Wärmedämm-Verbundsysteme | Fensteröffnung | 0 | 3.75 | NEW | 1155Wa 0000003096 | 0 | - | 0,51 | AllplanAttributes - U-Wert: 0.9; Schallschutzklasse: 32; Sonnenschutztyp: Movable
Fensteröffnung | H2 Ebene +1 | 1155Fen0000012058 | m² | 0 | Wärmedämm-Verbundsysteme | Fensteröffnung | 0 | 3.75 | NEW | 1155Wa 0000003092 | 0 | - | 0,51 | AllplanAttributes - U-Wert: 0.9; Schallschutzklasse: 32; Sonnenschutztyp: Movable
Fensteröffnung | H2 Ebene +1 | 1155Fen0000012043 | m² | 0 | Wärmedämm-Verbundsysteme | Fensteröffnung | 0 | 3.75 | NEW | 1155Wa 0000003092 | 0 | - | 0,51 | AllplanAttributes - U-Wert: 0.9; Schallschutzklasse: 32; Sonnenschutztyp: Movable
Fensteröffnung | H2 Ebene +1 | 1155Fen0000012045 | m² | 0 | Wärmedämm-Verbundsysteme | Fensteröffnung | 0 | 3.75 | NEW | 1155Wa 0000003088 | 0 | - | 0,51 | AllplanAttributes - U-Wert: 0.9; Schallschutzklasse: 32; Sonnenschutztyp: Movable
Fensteröffnung | H2 Ebene +1 | 1155Fen0000012060 | m² | 0 | Wärmedämm-Verbundsysteme | Fensteröffnung | 0 | 3.75 | NEW | 1155Wa 0000003088 | 0 | - | 0,51 | AllplanAttributes - U-Wert: 0.9; Schallschutzklasse: 32; Sonnenschutztyp: Movable
Fensteröffnung | H2 Ebene +1 | 1155Fen0000011882 | m² |  | Wärmedämm-Verbundsysteme | Fensteröffnung |  | 3.75 | NEW | 1155Wa 0000000332 | 0 | - | 0,51 | AllplanAttributes - Material: Fensterelement; Tragendes Bauteil: no; Brandabschnittsdefinierendes Bauteil: no; U-Wert: 0.9; Schallschutzklasse: 32; Sonnenschutztyp: Movable
Fensteröffnung | H2 Ebene +1 | 1155Fen0000011867 | m² |  | Wärmedämm-Verbundsysteme | Fensteröffnung |  | 3.75 | NEW | 1155Wa 0000000332 | 0 | - | 0,51 | AllplanAttributes - Material: Fensterelement; Tragendes Bauteil: no; Brandabschnittsdefinierendes Bauteil: no; U-Wert: 0.9; Schallschutzklasse: 32; Sonnenschutztyp: Movable
Fensteröffnung | H2 Ebene +1 | 1155Fen0000011870 | m³ | 0 | Wärmedämm-Verbundsysteme | Fensteröffnung | 0 | 3.75 | NEW | 1155Wa 0000000336 | 0 | - | 0,51 | AllplanAttributes - Material: Fensterelement; Außenliegend: yes; U-Wert: 0.9; Schallschutzklasse: 32; Sonnenschutztyp: Movable
Fensteröffnung | H2 Ebene +1 | 1155Fen0000011885 | m³ | 0 | Wärmedämm-Verbundsysteme | Fensteröffnung | 0 | 3.75 | NEW | 1155Wa 0000000336 | 0 | - | 0,51 | AllplanAttributes - Material: Fensterelement; Außenliegend: yes; U-Wert: 0.9; Schallschutzklasse: 32; Sonnenschutztyp: Movable
Fensteröffnung | H2 Ebene +1 | 1155Fen0000011872 | m³ | 0 | Wärmedämm-Verbundsysteme | Fensteröffnung | 0 | 3.75 | NEW | 1155Wa 0000000356 | 0 | - | 0,51 | AllplanAttributes - U-Wert: 0.9; Schallschutzklasse: 32; Sonnenschutztyp: Movable
Fensteröffnung | H2 Ebene +1 | 1155Fen0000011887 | m³ | 0 | Wärmedämm-Verbundsysteme | Fensteröffnung | 0 | 3.75 | NEW | 1155Wa 0000000356 | 0 | - | 0,51 | AllplanAttributes - U-Wert: 0.9; Schallschutzklasse: 32; Sonnenschutztyp: Movable
Fensteröffnung | H2 Ebene +1 | 1155Fen0000011889 | m² | 0 | Wärmedämm-Verbundsysteme | Fensteröffnung | 0 | 3.75 | NEW | 1155Wa 0000000352 | 0 | - | 0,51 | AllplanAttributes - U-Wert: 0.9; Schallschutzklasse: 32; Sonnenschutztyp: Movable
Fensteröffnung | H2 Ebene +1 | 1155Fen0000011874 | m² | 0 | Wärmedämm-Verbundsysteme | Fensteröffnung | 0 | 3.75 | NEW | 1155Wa 0000000352 | 0 | - | 0,51 | AllplanAttributes - U-Wert: 0.9; Schallschutzklasse: 32; Sonnenschutztyp: Movable
Fensteröffnung | H2 Ebene +1 | 1155Fen0000011876 | m² | 0 | Wärmedämm-Verbundsysteme | Fensteröffnung | 0 | 3.75 | NEW | 1155Wa 0000000348 | 0 | - | 0,51 | AllplanAttributes - U-Wert: 0.9; Schallschutzklasse: 32; Sonnenschutztyp: Movable
Fensteröffnung | H2 Ebene +1 | 1155Fen0000011891 | m² | 0 | Wärmedämm-Verbundsysteme | Fensteröffnung | 0 | 3.75 | NEW | 1155Wa 0000000348 | 0 | - | 0,51 | AllplanAttributes - U-Wert: 0.9; Schallschutzklasse: 32; Sonnenschutztyp: Movable
Fensteröffnung | H2 Ebene +1 | 1155Fen0000011878 | m² | 0 | Wärmedämm-Verbundsysteme | Fensteröffnung | 0 | 3.75 | NEW | 1155Wa 0000000344 | 0 | - | 0,51 | AllplanAttributes - U-Wert: 0.9; Schallschutzklasse: 32; Sonnenschutztyp: Movable
Fensteröffnung | H2 Ebene +1 | 1155Fen0000011893 | m² | 0 | Wärmedämm-Verbundsysteme | Fensteröffnung | 0 | 3.75 | NEW | 1155Wa 0000000344 | 0 | - | 0,51 | AllplanAttributes - U-Wert: 0.9; Schallschutzklasse: 32; Sonnenschutztyp: Movable
Fensteröffnung | H2 Ebene +1 | 1155Fen0000011880 | m² | 0 | Wärmedämm-Verbundsysteme | Fensteröffnung | 0 | 3.75 | NEW | 1155Wa 0000000340 | 0 | - | 0,51 | AllplanAttributes - U-Wert: 0.9; Schallschutzklasse: 32; Sonnenschutztyp: Movable
Fensteröffnung | H2 Ebene +1 | 1155Fen0000011895 | m² | 0 | Wärmedämm-Verbundsysteme | Fensteröffnung | 0 | 3.75 | NEW | 1155Wa 0000000340 | 0 | - | 0,51 | AllplanAttributes - U-Wert: 0.9; Schallschutzklasse: 32; Sonnenschutztyp: Movable
Fensteröffnung | H2 Ebene +1 | 1155Fen0000011912 | m² |  | Wärmedämm-Verbundsysteme | Fensteröffnung |  | 3.75 | NEW | 1155Wa 0000000388 | 0 | - | 0,51 | AllplanAttributes - Material: Fensterelement; Tragendes Bauteil: no; Brandabschnittsdefinierendes Bauteil: no; U-Wert: 0.9; Schallschutzklasse: 32; Sonnenschutztyp: Movable
Fensteröffnung | H2 Ebene +1 | 1155Fen0000011897 | m² |  | Wärmedämm-Verbundsysteme | Fensteröffnung |  | 3.75 | NEW | 1155Wa 0000000388 | 0 | - | 0,51 | AllplanAttributes - Material: Fensterelement; Tragendes Bauteil: no; Brandabschnittsdefinierendes Bauteil: no; U-Wert: 0.9; Schallschutzklasse: 32; Sonnenschutztyp: Movable
Fensteröffnung | H2 Ebene +1 | 1155Fen0000011915 | m³ | 0 | Wärmedämm-Verbundsysteme | Fensteröffnung | 0 | 3.75 | NEW | 1155Wa 0000000384 | 0 | - | 0,51 | AllplanAttributes - Material: Fensterelement; Außenliegend: yes; U-Wert: 0.9; Schallschutzklasse: 32; Sonnenschutztyp: Movable
Fensteröffnung | H2 Ebene +1 | 1155Fen0000011900 | m³ | 0 | Wärmedämm-Verbundsysteme | Fensteröffnung | 0 | 3.75 | NEW | 1155Wa 0000000384 | 0 | - | 0,51 | AllplanAttributes - Material: Fensterelement; Außenliegend: yes; U-Wert: 0.9; Schallschutzklasse: 32; Sonnenschutztyp: Movable
Fensteröffnung | H2 Ebene +1 | 1155Fen0000011917 | m³ | 0 | Wärmedämm-Verbundsysteme | Fensteröffnung | 0 | 3.75 | NEW | 1155Wa 0000000364 | 0 | - | 0,51 | AllplanAttributes - U-Wert: 0.9; Schallschutzklasse: 32; Sonnenschutztyp: Movable
Fensteröffnung | H2 Ebene +1 | 1155Fen0000011902 | m³ | 0 | Wärmedämm-Verbundsysteme | Fensteröffnung | 0 | 3.75 | NEW | 1155Wa 0000000364 | 0 | - | 0,51 | AllplanAttributes - U-Wert: 0.9; Schallschutzklasse: 32; Sonnenschutztyp: Movable
Fensteröffnung | H2 Ebene +1 | 1155Fen0000011904 | m² | 0 | Wärmedämm-Verbundsysteme | Fensteröffnung | 0 | 3.75 | NEW | 1155Wa 0000000368 | 0 | - | 0,51 | AllplanAttributes - U-Wert: 0.9; Schallschutzklasse: 32; Sonnenschutztyp: Movable
Fensteröffnung | H2 Ebene +1 | 1155Fen0000011919 | m² | 0 | Wärmedämm-Verbundsysteme | Fensteröffnung | 0 | 3.75 | NEW | 1155Wa 0000000368 | 0 | - | 0,51 | AllplanAttributes - U-Wert: 0.9; Schallschutzklasse: 32; Sonnenschutztyp: Movable
Fensteröffnung | H2 Ebene +1 | 1155Fen0000011921 | m² | 0 | Wärmedämm-Verbundsysteme | Fensteröffnung | 0 | 3.75 | NEW | 1155Wa 0000000372 | 0 | - | 0,51 | AllplanAttributes - U-Wert: 0.9; Schallschutzklasse: 32; Sonnenschutztyp: Movable
Fensteröffnung | H2 Ebene +1 | 1155Fen0000011906 | m² | 0 | Wärmedämm-Verbundsysteme | Fensteröffnung | 0 | 3.75 | NEW | 1155Wa 0000000372 | 0 | - | 0,51 | AllplanAttributes - U-Wert: 0.9; Schallschutzklasse: 32; Sonnenschutztyp: Movable
Fensteröffnung | H2 Ebene +1 | 1155Fen0000011908 | m² | 0 | Wärmedämm-Verbundsysteme | Fensteröffnung | 0 | 3.75 | NEW | 1155Wa 0000000376 | 0 | - | 0,51 | AllplanAttributes - U-Wert: 0.9; Schallschutzklasse: 32; Sonnenschutztyp: Movable
Fensteröffnung | H2 Ebene +1 | 1155Fen0000011923 | m² | 0 | Wärmedämm-Verbundsysteme | Fensteröffnung | 0 | 3.75 | NEW | 1155Wa 0000000376 | 0 | - | 0,51 | AllplanAttributes - U-Wert: 0.9; Schallschutzklasse: 32; Sonnenschutztyp: Movable
Fensteröffnung | H2 Ebene +1 | 1155Fen0000011925 | m² | 0 | Wärmedämm-Verbundsysteme | Fensteröffnung | 0 | 3.75 | NEW | 1155Wa 0000000380 | 0 | - | 0,51 | AllplanAttributes - U-Wert: 0.9; Schallschutzklasse: 32; Sonnenschutztyp: Movable
Fensteröffnung | H2 Ebene +1 | 1155Fen0000011910 | m² | 0 | Wärmedämm-Verbundsysteme | Fensteröffnung | 0 | 3.75 | NEW | 1155Wa 0000000380 | 0 | - | 0,51 | AllplanAttributes - U-Wert: 0.9; Schallschutzklasse: 32; Sonnenschutztyp: Movable
Fensteröffnung | H2 Ebene +1 | 1155Fen0000012212 | m² |  | Wärmedämm-Verbundsysteme | Fensteröffnung |  | 3.75 | NEW | 1155Wa 0000000706 | 0 | - | 0,51 | AllplanAttributes - Material: Fensterelement; Tragendes Bauteil: no; Brandabschnittsdefinierendes Bauteil: no; U-Wert: 0.9; Schallschutzklasse: 35; Sonnenschutztyp: Movable
Fensteröffnung | H2 Ebene +1 | 1155Fen0000012215 | m² |  | Wärmedämm-Verbundsysteme | Fensteröffnung |  | 3.75 | NEW | 1155Wa 0000000706 | 0 | - | 0,51 | AllplanAttributes - Material: Fensterelement; Tragendes Bauteil: no; Brandabschnittsdefinierendes Bauteil: no; U-Wert: 0.9; Schallschutzklasse: 35; Sonnenschutztyp: Movable
Fensteröffnung | H2 Ebene +1 | 1155Fen0000012228 | m³ | 0 | Wärmedämm-Verbundsysteme | Fensteröffnung | 0 | 3.75 | NEW | 1155Wa 0000000710 | 0 | - | 0,51 | AllplanAttributes - Material: Fensterelement; Außenliegend: yes; U-Wert: 0.9; Schallschutzklasse: 35; Sonnenschutztyp: Movable
Fensteröffnung | H2 Ebene +1 | 1155Fen0000012240 | m³ | 0 | Wärmedämm-Verbundsysteme | Fensteröffnung | 0 | 3.75 | NEW | 1155Wa 0000000710 | 0 | - | 0,51 | AllplanAttributes - Material: Fensterelement; Außenliegend: yes; U-Wert: 0.9; Schallschutzklasse: 35; Sonnenschutztyp: Movable
Fensteröffnung | H2 Ebene +1 | 1155Fen0000012226 | m³ | 0 | Wärmedämm-Verbundsysteme | Fensteröffnung | 0 | 3.75 | NEW | 1155Wa 0000000730 | 0 | - | 0,51 | AllplanAttributes - U-Wert: 0.9; Schallschutzklasse: 35; Sonnenschutztyp: Movable
Fensteröffnung | H2 Ebene +1 | 1155Fen0000012238 | m³ | 0 | Wärmedämm-Verbundsysteme | Fensteröffnung | 0 | 3.75 | NEW | 1155Wa 0000000730 | 0 | - | 0,51 | AllplanAttributes - U-Wert: 0.9; Schallschutzklasse: 35; Sonnenschutztyp: Movable
Fensteröffnung | H2 Ebene +1 | 1155Fen0000012224 | m² | 0 | Wärmedämm-Verbundsysteme | Fensteröffnung | 0 | 3.75 | NEW | 1155Wa 0000000726 | 0 | - | 0,51 | AllplanAttributes - U-Wert: 0.9; Schallschutzklasse: 35; Sonnenschutztyp: Movable
Fensteröffnung | H2 Ebene +1 | 1155Fen0000012236 | m² | 0 | Wärmedämm-Verbundsysteme | Fensteröffnung | 0 | 3.75 | NEW | 1155Wa 0000000726 | 0 | - | 0,51 | AllplanAttributes - U-Wert: 0.9; Schallschutzklasse: 35; Sonnenschutztyp: Movable
Fensteröffnung | H2 Ebene +1 | 1155Fen0000012234 | m² | 0 | Wärmedämm-Verbundsysteme | Fensteröffnung | 0 | 3.75 | NEW | 1155Wa 0000000722 | 0 | - | 0,51 | AllplanAttributes - U-Wert: 0.9; Schallschutzklasse: 35; Sonnenschutztyp: Movable
Fensteröffnung | H2 Ebene +1 | 1155Fen0000012222 | m² | 0 | Wärmedämm-Verbundsysteme | Fensteröffnung | 0 | 3.75 | NEW | 1155Wa 0000000722 | 0 | - | 0,51 | AllplanAttributes - U-Wert: 0.9; Schallschutzklasse: 35; Sonnenschutztyp: Movable
Fensteröffnung | H2 Ebene +1 | 1155Fen0000012220 | m² | 0 | Wärmedämm-Verbundsysteme | Fensteröffnung | 0 | 3.75 | NEW | 1155Wa 0000000718 | 0 | - | 0,51 | AllplanAttributes - U-Wert: 0.9; Schallschutzklasse: 35; Sonnenschutztyp: Movable
Fensteröffnung | H2 Ebene +1 | 1155Fen0000012232 | m² | 0 | Wärmedämm-Verbundsysteme | Fensteröffnung | 0 | 3.75 | NEW | 1155Wa 0000000718 | 0 | - | 0,51 | AllplanAttributes - U-Wert: 0.9; Schallschutzklasse: 35; Sonnenschutztyp: Movable
Fensteröffnung | H2 Ebene +1 | 1155Fen0000012230 | m² | 0 | Wärmedämm-Verbundsysteme | Fensteröffnung | 0 | 3.75 | NEW | 1155Wa 0000000714 | 0 | - | 0,51 | AllplanAttributes - U-Wert: 0.9; Schallschutzklasse: 35; Sonnenschutztyp: Movable
Fensteröffnung | H2 Ebene +1 | 1155Fen0000012218 | m² | 0 | Wärmedämm-Verbundsysteme | Fensteröffnung | 0 | 3.75 | NEW | 1155Wa 0000000714 | 0 | - | 0,51 | AllplanAttributes - U-Wert: 0.9; Schallschutzklasse: 35; Sonnenschutztyp: Movable
Fensteröffnung | H2 Ebene +1 | 1155Fen0000012167 | m² |  | Wärmedämm-Verbundsysteme | Fensteröffnung |  | 3.75 | NEW | 1155Wa 0000000762 | 0 | - | 0,51 | AllplanAttributes - Material: Fensterelement; Tragendes Bauteil: no; Brandabschnittsdefinierendes Bauteil: no; U-Wert: 0.9; Schallschutzklasse: 35; Sonnenschutztyp: Movable
Fensteröffnung | H2 Ebene +1 | 1155Fen0000012170 | m² |  | Wärmedämm-Verbundsysteme | Fensteröffnung |  | 3.75 | NEW | 1155Wa 0000000762 | 0 | - | 0,51 | AllplanAttributes - Material: Fensterelement; Tragendes Bauteil: no; Brandabschnittsdefinierendes Bauteil: no; U-Wert: 0.9; Schallschutzklasse: 35; Sonnenschutztyp: Movable
Fensteröffnung | H2 Ebene +1 | 1155Fen0000012186 | m³ | 0 | Wärmedämm-Verbundsysteme | Fensteröffnung | 0 | 3.75 | NEW | 1155Wa 0000000758 | 0 | - | 0,51 | AllplanAttributes - Material: Fensterelement; Außenliegend: yes; U-Wert: 0.9; Schallschutzklasse: 35; Sonnenschutztyp: Movable
Fensteröffnung | H2 Ebene +1 | 1155Fen0000012198 | m³ | 0 | Wärmedämm-Verbundsysteme | Fensteröffnung | 0 | 3.75 | NEW | 1155Wa 0000000758 | 0 | - | 0,51 | AllplanAttributes - Material: Fensterelement; Außenliegend: yes; U-Wert: 0.9; Schallschutzklasse: 35; Sonnenschutztyp: Movable
Fensteröffnung | H2 Ebene +1 | 1155Fen0000012196 | m³ | 0 | Wärmedämm-Verbundsysteme | Fensteröffnung | 0 | 3.75 | NEW | 1155Wa 0000000738 | 0 | - | 0,51 | AllplanAttributes - U-Wert: 0.9; Schallschutzklasse: 35; Sonnenschutztyp: Movable
Fensteröffnung | H2 Ebene +1 | 1155Fen0000012184 | m³ | 0 | Wärmedämm-Verbundsysteme | Fensteröffnung | 0 | 3.75 | NEW | 1155Wa 0000000738 | 0 | - | 0,51 | AllplanAttributes - U-Wert: 0.9; Schallschutzklasse: 35; Sonnenschutztyp: Movable
Fensteröffnung | H2 Ebene +1 | 1155Fen0000012194 | m² | 0 | Wärmedämm-Verbundsysteme | Fensteröffnung | 0 | 3.75 | NEW | 1155Wa 0000000742 | 0 | - | 0,51 | AllplanAttributes - U-Wert: 0.9; Schallschutzklasse: 35; Sonnenschutztyp: Movable
Fensteröffnung | H2 Ebene +1 | 1155Fen0000012182 | m² | 0 | Wärmedämm-Verbundsysteme | Fensteröffnung | 0 | 3.75 | NEW | 1155Wa 0000000742 | 0 | - | 0,51 | AllplanAttributes - U-Wert: 0.9; Schallschutzklasse: 35; Sonnenschutztyp: Movable
Fensteröffnung | H2 Ebene +1 | 1155Fen0000012180 | m² | 0 | Wärmedämm-Verbundsysteme | Fensteröffnung | 0 | 3.75 | NEW | 1155Wa 0000000746 | 0 | - | 0,51 | AllplanAttributes - U-Wert: 0.9; Schallschutzklasse: 35; Sonnenschutztyp: Movable
Fensteröffnung | H2 Ebene +1 | 1155Fen0000012192 | m² | 0 | Wärmedämm-Verbundsysteme | Fensteröffnung | 0 | 3.75 | NEW | 1155Wa 0000000746 | 0 | - | 0,51 | AllplanAttributes - U-Wert: 0.9; Schallschutzklasse: 35; Sonnenschutztyp: Movable
Fensteröffnung | H2 Ebene +1 | 1155Fen0000012190 | m² | 0 | Wärmedämm-Verbundsysteme | Fensteröffnung | 0 | 3.75 | NEW | 1155Wa 0000000750 | 0 | - | 0,51 | AllplanAttributes - U-Wert: 0.9; Schallschutzklasse: 35; Sonnenschutztyp: Movable
Fensteröffnung | H2 Ebene +1 | 1155Fen0000012178 | m² | 0 | Wärmedämm-Verbundsysteme | Fensteröffnung | 0 | 3.75 | NEW | 1155Wa 0000000750 | 0 | - | 0,51 | AllplanAttributes - U-Wert: 0.9; Schallschutzklasse: 35; Sonnenschutztyp: Movable
Fensteröffnung | H2 Ebene +1 | 1155Fen0000012188 | m² | 0 | Wärmedämm-Verbundsysteme | Fensteröffnung | 0 | 3.75 | NEW | 1155Wa 0000000754 | 0 | - | 0,51 | AllplanAttributes - U-Wert: 0.9; Schallschutzklasse: 35; Sonnenschutztyp: Movable
Fensteröffnung | H2 Ebene +1 | 1155Fen0000012176 | m² | 0 | Wärmedämm-Verbundsysteme | Fensteröffnung | 0 | 3.75 | NEW | 1155Wa 0000000754 | 0 | - | 0,51 | AllplanAttributes - U-Wert: 0.9; Schallschutzklasse: 35; Sonnenschutztyp: Movable
Fensteröffnung | H2 Ebene +1 | 1155Fen0000012173 | m² |  | Wärmedämm-Verbundsysteme | Fensteröffnung |  | 3.75 | NEW | 1155Wa 0000002063 | 0 | - | 0,51 | AllplanAttributes - Material: Fensterelement; Tragendes Bauteil: no; Brandabschnittsdefinierendes Bauteil: no; U-Wert: 0.9; Schallschutzklasse: 32; Sonnenschutztyp: Movable
Fensteröffnung | H2 Ebene +1 | 1155Fen0000012210 | m³ | 0 | Wärmedämm-Verbundsysteme | Fensteröffnung | 0 | 3.75 | NEW | 1155Wa 0000002059 | 0 | - | 0,51 | AllplanAttributes - Material: Fensterelement; Außenliegend: yes; U-Wert: 0.9; Schallschutzklasse: 32; Sonnenschutztyp: Movable
Fensteröffnung | H2 Ebene +1 | 1155Fen0000012208 | m³ | 0 | Wärmedämm-Verbundsysteme | Fensteröffnung | 0 | 3.75 | NEW | 1155Wa 0000002055 | 0 | - | 0,51 | AllplanAttributes - U-Wert: 0.9; Schallschutzklasse: 32; Sonnenschutztyp: Movable
Fensteröffnung | H2 Ebene +1 | 1155Fen0000012206 | m² | 0 | Wärmedämm-Verbundsysteme | Fensteröffnung | 0 | 3.75 | NEW | 1155Wa 0000002051 | 0 | - | 0,51 | AllplanAttributes - U-Wert: 0.9; Schallschutzklasse: 32; Sonnenschutztyp: Movable
Fensteröffnung | H2 Ebene +1 | 1155Fen0000012204 | m² | 0 | Wärmedämm-Verbundsysteme | Fensteröffnung | 0 | 3.75 | NEW | 1155Wa 0000002047 | 0 | - | 0,51 | AllplanAttributes - U-Wert: 0.9; Schallschutzklasse: 32; Sonnenschutztyp: Movable
Fensteröffnung | H2 Ebene +1 | 1155Fen0000012202 | m² | 0 | Wärmedämm-Verbundsysteme | Fensteröffnung | 0 | 3.75 | NEW | 1155Wa 0000002043 | 0 | - | 0,51 | AllplanAttributes - U-Wert: 0.9; Schallschutzklasse: 32; Sonnenschutztyp: Movable
Fensteröffnung | H2 Ebene +1 | 1155Fen0000012200 | m² | 0 | Wärmedämm-Verbundsysteme | Fensteröffnung | 0 | 3.75 | NEW | 1155Wa 0000002039 | 0 | - | 0,51 | AllplanAttributes - U-Wert: 0.9; Schallschutzklasse: 32; Sonnenschutztyp: Movable
Türöffnung | H2 Ebene +1 | 1155Tür0000002411 | m² |  | Trockenbauarbeiten | Türöffnung |  | 3.75 | NEW | 1155Wa 0000002623 | 0 | - | 0,51 | AllplanAttributes - U-Wert: 0.9; Schallschutzklasse: 32; Sonnenschutztyp: Movable; Codetext: Codetext; Türanschlag: DIN R; Pset_OpeningElementCommon - FireExit: no; Reference: Codetext
Türöffnung | H2 Ebene +1 | 1155Tür0000002413 | m³ | 0 | Trockenbauarbeiten | Türöffnung | 0 | 3.75 | NEW | 1155Wa 0000002619 | 0 | - | 0,51 | AllplanAttributes - U-Wert: 0.9; Schallschutzklasse: 32; Sonnenschutztyp: Movable; Türanschlag: DIN R
Türöffnung | H2 Ebene +1 | 1155Tür0000002415 | m³ | 0 | Trockenbauarbeiten | Türöffnung | 0 | 3.75 | NEW | 1155Wa 0000002614 | 0 | - | 0,51 | AllplanAttributes - U-Wert: 0.9; Schallschutzklasse: 32; Sonnenschutztyp: Movable; Türanschlag: DIN R
Türöffnung | H2 Ebene +1 | 1155Tür0000002417 | m² | 0 | Trockenbauarbeiten | Türöffnung | 0 | 3.75 | NEW | 1155Wa 0000002609 | 0 | - | 0,51 | AllplanAttributes - U-Wert: 0.9; Schallschutzklasse: 32; Sonnenschutztyp: Movable; Türanschlag: DIN R
Türöffnung | H2 Ebene +1 | 1155Tür0000002419 | m² | 0 | Trockenbauarbeiten | Türöffnung | 0 | 3.75 | NEW | 1155Wa 0000002605 | 0 | - | 0,51 | AllplanAttributes - U-Wert: 0.9; Schallschutzklasse: 32; Sonnenschutztyp: Movable; Türanschlag: DIN R
Türöffnung | H2 Ebene +1 | 1155Tür0000002421 | m² | 0 | Trockenbauarbeiten | Türöffnung | 0 | 3.75 | NEW | 1155Wa 0000002601 | 0 | - | 0,51 | AllplanAttributes - U-Wert: 0.9; Schallschutzklasse: 32; Sonnenschutztyp: Movable; Türanschlag: DIN R
Türöffnung | H2 Ebene +1 | 1155Tür0000002502 | m² | 0 | Trockenbauarbeiten | Türöffnung | 0 | 3.75 | NEW | 1155Wa 0000002680 | 0 | - | 0,51 | AllplanAttributes - U-Wert: 0.9; Schallschutzklasse: 32; Sonnenschutztyp: Movable; Türanschlag: DIN R
Fensteröffnung | H2 Ebene +1 | 1155Fen0000005493 | m² |  | Fensterarbeiten | Fensteröffnung |  | 3.75 |  | 1155Wa 0000002907 | 0 | - | 0,51 | AllplanAttributes - U-Wert: 0.9; Schallschutzklasse: 32; Sonnenschutztyp: Movable
Fensteröffnung | H2 Ebene +1 | 1155Fen0000002857 | m³ | 0 | Fensterarbeiten | Fensteröffnung | 0 | 3.75 |  | 1155Wa 0000002903 | 0 | - | 0,51 | AllplanAttributes - U-Wert: 0.9; Schallschutzklasse: 32; Sonnenschutztyp: Movable
Fensteröffnung | H2 Ebene +1 | 1155Fen0000002859 | m³ | 0 | Fensterarbeiten | Fensteröffnung | 0 | 3.75 |  | 1155Wa 0000002899 | 0 | - | 0,51 | AllplanAttributes - U-Wert: 0.9; Schallschutzklasse: 32; Sonnenschutztyp: Movable
Fensteröffnung | H2 Ebene +1 | 1155Fen0000002849 | m² | 0 | Fensterarbeiten | Fensteröffnung | 0 | 3.75 |  | 1155Wa 0000002895 | 0 | - | 0,51 | AllplanAttributes - U-Wert: 0.9; Schallschutzklasse: 32; Sonnenschutztyp: Movable
Fensteröffnung | H2 Ebene +1 | 1155Fen0000002851 | m² | 0 | Fensterarbeiten | Fensteröffnung | 0 | 3.75 | NEW | 1155Wa 0000002891 | 0 | - | 0,51 | AllplanAttributes - U-Wert: 0.9; Schallschutzklasse: 32; Sonnenschutztyp: Movable
Fensteröffnung | H2 Ebene +1 | 1155Fen0000002853 | m² | 0 | Fensterarbeiten | Fensteröffnung | 0 | 3.75 | NEW | 1155Wa 0000002887 | 0 | - | 0,51 | AllplanAttributes - U-Wert: 0.9; Schallschutzklasse: 32; Sonnenschutztyp: Movable
Fensteröffnung | H2 Ebene +1 | 1155Fen0000002855 | m² | 0 | Fensterarbeiten | Fensteröffnung | 0 | 3.75 | NEW | 1155Wa 0000002883 | 0 | - | 0,51 | AllplanAttributes - U-Wert: 0.9; Schallschutzklasse: 32; Sonnenschutztyp: Movable
Fensteröffnung | H2 Ebene +1 | 1155Fen0000005498 | m² |  | Fensterarbeiten | Fensteröffnung |  | 3.75 |  | 1155Wa 0000003057 | 0 | - | 0,51 | AllplanAttributes - U-Wert: 0.9; Schallschutzklasse: 32; Sonnenschutztyp: Movable
Fensteröffnung | H2 Ebene +1 | 1155Fen0000003000 | m³ | 0 | Fensterarbeiten | Fensteröffnung | 0 | 3.75 |  | 1155Wa 0000003053 | 0 | - | 0,51 | AllplanAttributes - U-Wert: 0.9; Schallschutzklasse: 32; Sonnenschutztyp: Movable
Fensteröffnung | H2 Ebene +1 | 1155Fen0000002998 | m³ | 0 | Fensterarbeiten | Fensteröffnung | 0 | 3.75 |  | 1155Wa 0000003049 | 0 | - | 0,51 | AllplanAttributes - U-Wert: 0.9; Schallschutzklasse: 32; Sonnenschutztyp: Movable
Fensteröffnung | H2 Ebene +1 | 1155Fen0000003008 | m² | 0 | Fensterarbeiten | Fensteröffnung | 0 | 3.75 |  | 1155Wa 0000003045 | 0 | - | 0,51 | AllplanAttributes - U-Wert: 0.9; Schallschutzklasse: 32; Sonnenschutztyp: Movable
Fensteröffnung | H2 Ebene +1 | 1155Fen0000003006 | m² | 0 | Fensterarbeiten | Fensteröffnung | 0 | 3.75 | NEW | 1155Wa 0000003041 | 0 | - | 0,51 | AllplanAttributes - U-Wert: 0.9; Schallschutzklasse: 32; Sonnenschutztyp: Movable
Fensteröffnung | H2 Ebene +1 | 1155Fen0000003004 | m² | 0 | Fensterarbeiten | Fensteröffnung | 0 | 3.75 | NEW | 1155Wa 0000003037 | 0 | - | 0,51 | AllplanAttributes - U-Wert: 0.9; Schallschutzklasse: 32; Sonnenschutztyp: Movable
Fensteröffnung | H2 Ebene +1 | 1155Fen0000003002 | m² | 0 | Fensterarbeiten | Fensteröffnung | 0 | 3.75 | NEW | 1155Wa 0000003033 | 0 | - | 0,51 | AllplanAttributes - U-Wert: 0.9; Schallschutzklasse: 32; Sonnenschutztyp: Movable
Fensteröffnung | H2 Ebene +1 | 1155Fen0000005597 | m² | 0 | Fensterarbeiten | Fensteröffnung | 0 | 3.75 |  | 1155Wa 0000003947 | 0 | - | 0,51 | AllplanAttributes - U-Wert: 0.9; Schallschutzklasse: 32; Sonnenschutztyp: Movable
Fensteröffnung | H2 Ebene +1 | 1155Fen0000005609 | m² | 0 | Fensterarbeiten | Fensteröffnung | 0 | 3.75 |  | 1155Wa 0000003947 | 0 | - | 0,51 | AllplanAttributes - U-Wert: 0.9; Schallschutzklasse: 32; Sonnenschutztyp: Movable
Fensteröffnung | H2 Ebene +1 | 1155Fen2005719872 | m² | 0 | Fensterarbeiten | Fensteröffnung | 0 | 3.75 |  | 1155Wa 0000003947 | 0 | - | 0,51 | AllplanAttributes - U-Wert: 0.9; Schallschutzklasse: 32; Sonnenschutztyp: Movable
Fensteröffnung | H2 Ebene +1 | 1155Fen0000005613 | m² | 0 | Fensterarbeiten | Fensteröffnung | 0 | 3.75 |  | 1155Wa 0000003947 | 0 | - | 0,51 | AllplanAttributes - U-Wert: 0.9; Schallschutzklasse: 32; Sonnenschutztyp: Movable
Fensteröffnung | H2 Ebene +1 | 1155Fen0000005617 | m² | 0 | Fensterarbeiten | Fensteröffnung | 0 | 3.75 |  | 1155Wa 0000003947 | 0 | - | 0,51 | AllplanAttributes - U-Wert: 0.9; Schallschutzklasse: 32; Sonnenschutztyp: Movable
Fensteröffnung | H2 Ebene +1 | 1155Fen0000003697 | m³ | 0 | Fensterarbeiten | Fensteröffnung | 0 | 3.75 |  | 1155Wa 0000003957 | 0 | - | 0,51 | AllplanAttributes - U-Wert: 0.9; Schallschutzklasse: 32; Sonnenschutztyp: Movable
Fensteröffnung | H2 Ebene +1 | 1155Fen0000003709 | m³ | 0 | Fensterarbeiten | Fensteröffnung | 0 | 3.75 |  | 1155Wa 0000003957 | 0 | - | 0,51 | AllplanAttributes - U-Wert: 0.9; Schallschutzklasse: 32; Sonnenschutztyp: Movable
Fensteröffnung | H2 Ebene +1 | 1155Fen2005719866 | m³ | 0 | Fensterarbeiten | Fensteröffnung | 0 | 3.75 |  | 1155Wa 0000003957 | 0 | - | 0,51 | AllplanAttributes - U-Wert: 0.9; Schallschutzklasse: 32; Sonnenschutztyp: Movable
Fensteröffnung | H2 Ebene +1 | 1155Fen0000003717 | m³ | 0 | Fensterarbeiten | Fensteröffnung | 0 | 3.75 |  | 1155Wa 0000003957 | 0 | - | 0,51 | AllplanAttributes - U-Wert: 0.9; Schallschutzklasse: 32; Sonnenschutztyp: Movable
Fensteröffnung | H2 Ebene +1 | 1155Fen0000003713 | m³ | 0 | Fensterarbeiten | Fensteröffnung | 0 | 3.75 |  | 1155Wa 0000003957 | 0 | - | 0,51 | AllplanAttributes - U-Wert: 0.9; Schallschutzklasse: 32; Sonnenschutztyp: Movable
Fensteröffnung | H2 Ebene +1 | 1155Fen0000003699 | m³ | 0 | Fensterarbeiten | Fensteröffnung | 0 | 3.75 |  | 1155Wa 0000003966 | 0 | - | 0,51 | AllplanAttributes - U-Wert: 0.9; Schallschutzklasse: 32; Sonnenschutztyp: Movable
Fensteröffnung | H2 Ebene +1 | 1155Fen0000003711 | m³ | 0 | Fensterarbeiten | Fensteröffnung | 0 | 3.75 |  | 1155Wa 0000003966 | 0 | - | 0,51 | AllplanAttributes - U-Wert: 0.9; Schallschutzklasse: 32; Sonnenschutztyp: Movable
Fensteröffnung | H2 Ebene +1 | 1155Fen2005719865 | m³ | 0 | Fensterarbeiten | Fensteröffnung | 0 | 3.75 |  | 1155Wa 0000003966 | 0 | - | 0,51 | AllplanAttributes - U-Wert: 0.9; Schallschutzklasse: 32; Sonnenschutztyp: Movable
Fensteröffnung | H2 Ebene +1 | 1155Fen0000003719 | m³ | 0 | Fensterarbeiten | Fensteröffnung | 0 | 3.75 |  | 1155Wa 0000003966 | 0 | - | 0,51 | AllplanAttributes - U-Wert: 0.9; Schallschutzklasse: 32; Sonnenschutztyp: Movable
Fensteröffnung | H2 Ebene +1 | 1155Fen0000003715 | m³ | 0 | Fensterarbeiten | Fensteröffnung | 0 | 3.75 |  | 1155Wa 0000003966 | 0 | - | 0,51 | AllplanAttributes - U-Wert: 0.9; Schallschutzklasse: 32; Sonnenschutztyp: Movable
Fensteröffnung | H2 Ebene +1 | 1155Fen0000003645 | m² | 0 | Fensterarbeiten | Fensteröffnung | 0 | 3.75 |  | 1155Wa 0000003976 | 0 | - | 0,51 | AllplanAttributes - U-Wert: 0.9; Schallschutzklasse: 32; Sonnenschutztyp: Movable
Fensteröffnung | H2 Ebene +1 | 1155Fen0000003669 | m² | 0 | Fensterarbeiten | Fensteröffnung | 0 | 3.75 |  | 1155Wa 0000003976 | 0 | - | 0,51 | AllplanAttributes - U-Wert: 0.9; Schallschutzklasse: 32; Sonnenschutztyp: Movable
Fensteröffnung | H2 Ebene +1 | 1155Fen2005719864 | m² | 0 | Fensterarbeiten | Fensteröffnung | 0 | 3.75 |  | 1155Wa 0000003976 | 0 | - | 0,51 | AllplanAttributes - U-Wert: 0.9; Schallschutzklasse: 32; Sonnenschutztyp: Movable
Fensteröffnung | H2 Ebene +1 | 1155Fen0000003685 | m² | 0 | Fensterarbeiten | Fensteröffnung | 0 | 3.75 |  | 1155Wa 0000003976 | 0 | - | 0,51 | AllplanAttributes - U-Wert: 0.9; Schallschutzklasse: 32; Sonnenschutztyp: Movable
Fensteröffnung | H2 Ebene +1 | 1155Fen0000003677 | m² | 0 | Fensterarbeiten | Fensteröffnung | 0 | 3.75 |  | 1155Wa 0000003976 | 0 | - | 0,51 | AllplanAttributes - U-Wert: 0.9; Schallschutzklasse: 32; Sonnenschutztyp: Movable
Fensteröffnung | H2 Ebene +1 | 1155Fen0000003647 | m² | 0 | Fensterarbeiten | Fensteröffnung | 0 | 3.75 | NEW | 1155Wa 0000003986 | 0 | - | 0,51 | AllplanAttributes - U-Wert: 0.9; Schallschutzklasse: 32; Sonnenschutztyp: Movable
Fensteröffnung | H2 Ebene +1 | 1155Fen0000003671 | m² | 0 | Fensterarbeiten | Fensteröffnung | 0 | 3.75 | NEW | 1155Wa 0000003986 | 0 | - | 0,51 | AllplanAttributes - U-Wert: 0.9; Schallschutzklasse: 32; Sonnenschutztyp: Movable
Fensteröffnung | H2 Ebene +1 | 1155Fen2005719863 | m² | 0 | Fensterarbeiten | Fensteröffnung | 0 | 3.75 | NEW | 1155Wa 0000003986 | 0 | - | 0,51 | AllplanAttributes - U-Wert: 0.9; Schallschutzklasse: 32; Sonnenschutztyp: Movable
Fensteröffnung | H2 Ebene +1 | 1155Fen0000003687 | m² | 0 | Fensterarbeiten | Fensteröffnung | 0 | 3.75 | NEW | 1155Wa 0000003986 | 0 | - | 0,51 | AllplanAttributes - U-Wert: 0.9; Schallschutzklasse: 32; Sonnenschutztyp: Movable
Fensteröffnung | H2 Ebene +1 | 1155Fen0000003679 | m² | 0 | Fensterarbeiten | Fensteröffnung | 0 | 3.75 | NEW | 1155Wa 0000003986 | 0 | - | 0,51 | AllplanAttributes - U-Wert: 0.9; Schallschutzklasse: 32; Sonnenschutztyp: Movable
Fensteröffnung | H2 Ebene +1 | 1155Fen0000003649 | m² | 0 | Fensterarbeiten | Fensteröffnung | 0 | 3.75 | NEW | 1155Wa 0000003996 | 0 | - | 0,51 | AllplanAttributes - U-Wert: 0.9; Schallschutzklasse: 32; Sonnenschutztyp: Movable
Fensteröffnung | H2 Ebene +1 | 1155Fen0000003673 | m² | 0 | Fensterarbeiten | Fensteröffnung | 0 | 3.75 | NEW | 1155Wa 0000003996 | 0 | - | 0,51 | AllplanAttributes - U-Wert: 0.9; Schallschutzklasse: 32; Sonnenschutztyp: Movable
Fensteröffnung | H2 Ebene +1 | 1155Fen2005719862 | m² | 0 | Fensterarbeiten | Fensteröffnung | 0 | 3.75 | NEW | 1155Wa 0000003996 | 0 | - | 0,51 | AllplanAttributes - U-Wert: 0.9; Schallschutzklasse: 32; Sonnenschutztyp: Movable
Fensteröffnung | H2 Ebene +1 | 1155Fen0000003689 | m² | 0 | Fensterarbeiten | Fensteröffnung | 0 | 3.75 | NEW | 1155Wa 0000003996 | 0 | - | 0,51 | AllplanAttributes - U-Wert: 0.9; Schallschutzklasse: 32; Sonnenschutztyp: Movable
Fensteröffnung | H2 Ebene +1 | 1155Fen0000003681 | m² | 0 | Fensterarbeiten | Fensteröffnung | 0 | 3.75 | NEW | 1155Wa 0000003996 | 0 | - | 0,51 | AllplanAttributes - U-Wert: 0.9; Schallschutzklasse: 32; Sonnenschutztyp: Movable
Fensteröffnung | H2 Ebene +1 | 1155Fen0000003651 | m² | 0 | Fensterarbeiten | Fensteröffnung | 0 | 3.75 | NEW | 1155Wa 0000004006 | 0 | - | 0,51 | AllplanAttributes - U-Wert: 0.9; Schallschutzklasse: 32; Sonnenschutztyp: Movable
Fensteröffnung | H2 Ebene +1 | 1155Fen0000003675 | m² | 0 | Fensterarbeiten | Fensteröffnung | 0 | 3.75 | NEW | 1155Wa 0000004006 | 0 | - | 0,51 | AllplanAttributes - U-Wert: 0.9; Schallschutzklasse: 32; Sonnenschutztyp: Movable
Fensteröffnung | H2 Ebene +1 | 1155Fen2005719861 | m² | 0 | Fensterarbeiten | Fensteröffnung | 0 | 3.75 | NEW | 1155Wa 0000004006 | 0 | - | 0,51 | AllplanAttributes - U-Wert: 0.9; Schallschutzklasse: 32; Sonnenschutztyp: Movable
Fensteröffnung | H2 Ebene +1 | 1155Fen0000003691 | m² | 0 | Fensterarbeiten | Fensteröffnung | 0 | 3.75 | NEW | 1155Wa 0000004006 | 0 | - | 0,51 | AllplanAttributes - U-Wert: 0.9; Schallschutzklasse: 32; Sonnenschutztyp: Movable
Fensteröffnung | H2 Ebene +1 | 1155Fen0000003683 | m² | 0 | Fensterarbeiten | Fensteröffnung | 0 | 3.75 | NEW | 1155Wa 0000004006 | 0 | - | 0,51 | AllplanAttributes - U-Wert: 0.9; Schallschutzklasse: 32; Sonnenschutztyp: Movable
Fensteröffnung | H2 Ebene +1 | 1155Fen2005783713 | m² | 0 | Fensterarbeiten | Fensteröffnung | 0 | 3.75 |  | 1155Wa 0000004406 | 0 | - | 0,51 | AllplanAttributes - U-Wert: 0.9; Schallschutzklasse: 32; Sonnenschutztyp: Movable
Fensteröffnung | H2 Ebene +1 | 1155Fen2005783712 | m³ | 0 | Fensterarbeiten | Fensteröffnung | 0 | 3.75 |  | 1155Wa 0000004410 | 0 | - | 0,51 | AllplanAttributes - U-Wert: 0.9; Schallschutzklasse: 32; Sonnenschutztyp: Movable
Fensteröffnung | H2 Ebene +1 | 1155Fen2005783711 | m³ | 0 | Fensterarbeiten | Fensteröffnung | 0 | 3.75 |  | 1155Wa 0000004402 | 0 | - | 0,51 | AllplanAttributes - U-Wert: 0.9; Schallschutzklasse: 32; Sonnenschutztyp: Movable
Fensteröffnung | H2 Ebene +1 | 1155Fen2005783710 | m² | 0 | Fensterarbeiten | Fensteröffnung | 0 | 3.75 |  | 1155Wa 0000004398 | 0 | - | 0,51 | AllplanAttributes - U-Wert: 0.9; Schallschutzklasse: 32; Sonnenschutztyp: Movable
Fensteröffnung | H2 Ebene +1 | 1155Fen2005783709 | m² | 0 | Fensterarbeiten | Fensteröffnung | 0 | 3.75 | NEW | 1155Wa 0000004394 | 0 | - | 0,51 | AllplanAttributes - U-Wert: 0.9; Schallschutzklasse: 32; Sonnenschutztyp: Movable
Fensteröffnung | H2 Ebene +1 | 1155Fen2005783708 | m² | 0 | Fensterarbeiten | Fensteröffnung | 0 | 3.75 | NEW | 1155Wa 0000004390 | 0 | - | 0,51 | AllplanAttributes - U-Wert: 0.9; Schallschutzklasse: 32; Sonnenschutztyp: Movable
Fensteröffnung | H2 Ebene +1 | 1155Fen2005783707 | m² | 0 | Fensterarbeiten | Fensteröffnung | 0 | 3.75 | NEW | 1155Wa 0000004416 | 0 | - | 0,51 | AllplanAttributes - U-Wert: 0.9; Schallschutzklasse: 32; Sonnenschutztyp: Movable
Fensteröffnung | H2 Ebene +1 | 1155Fen2005796554 | m² | 0 | Fensterarbeiten | Fensteröffnung | 0 | 3.75 |  | 1155Wa 0000004611 | 0 | - | 0,51 | AllplanAttributes - U-Wert: 0.9; Schallschutzklasse: 32; Sonnenschutztyp: Movable
Fensteröffnung | H2 Ebene +1 | 1155Fen2005796553 | m³ | 0 | Fensterarbeiten | Fensteröffnung | 0 | 3.75 |  | 1155Wa 0000004607 | 0 | - | 0,51 | AllplanAttributes - U-Wert: 0.9; Schallschutzklasse: 32; Sonnenschutztyp: Movable
Fensteröffnung | H2 Ebene +1 | 1155Fen2005796552 | m³ | 0 | Fensterarbeiten | Fensteröffnung | 0 | 3.75 |  | 1155Wa 0000004603 | 0 | - | 0,51 | AllplanAttributes - U-Wert: 0.9; Schallschutzklasse: 32; Sonnenschutztyp: Movable
Fensteröffnung | H2 Ebene +1 | 1155Fen2005796551 | m² | 0 | Fensterarbeiten | Fensteröffnung | 0 | 3.75 |  | 1155Wa 0000004599 | 0 | - | 0,51 | AllplanAttributes - U-Wert: 0.9; Schallschutzklasse: 32; Sonnenschutztyp: Movable
Fensteröffnung | H2 Ebene +1 | 1155Fen2005796550 | m² | 0 | Fensterarbeiten | Fensteröffnung | 0 | 3.75 | NEW | 1155Wa 0000004595 | 0 | - | 0,51 | AllplanAttributes - U-Wert: 0.9; Schallschutzklasse: 32; Sonnenschutztyp: Movable
Fensteröffnung | H2 Ebene +1 | 1155Fen2005796549 | m² | 0 | Fensterarbeiten | Fensteröffnung | 0 | 3.75 | NEW | 1155Wa 0000004591 | 0 | - | 0,51 | AllplanAttributes - U-Wert: 0.9; Schallschutzklasse: 32; Sonnenschutztyp: Movable
Fensteröffnung | H2 Ebene +1 | 1155Fen2005796548 | m² | 0 | Fensterarbeiten | Fensteröffnung | 0 | 3.75 | NEW | 1155Wa 0000004587 | 0 | - | 0,51 | AllplanAttributes - U-Wert: 0.9; Schallschutzklasse: 32; Sonnenschutztyp: Movable
Fensteröffnung | H2 Ebene +1 | 1155Fen2005796784 | m² | 0 | Fensterarbeiten | Fensteröffnung | 0 | 3.75 |  | 1155Wa 0000004689 | 0 | - | 0,51 | AllplanAttributes - U-Wert: 0.9; Schallschutzklasse: 32; Sonnenschutztyp: Movable
Fensteröffnung | H2 Ebene +1 | 1155Fen2005796783 | m³ | 0 | Fensterarbeiten | Fensteröffnung | 0 | 3.75 |  | 1155Wa 0000004693 | 0 | - | 0,51 | AllplanAttributes - U-Wert: 0.9; Schallschutzklasse: 32; Sonnenschutztyp: Movable
Fensteröffnung | H2 Ebene +1 | 1155Fen2005796782 | m³ | 0 | Fensterarbeiten | Fensteröffnung | 0 | 3.75 |  | 1155Wa 0000004697 | 0 | - | 0,51 | AllplanAttributes - U-Wert: 0.9; Schallschutzklasse: 32; Sonnenschutztyp: Movable
Fensteröffnung | H2 Ebene +1 | 1155Fen2005796781 | m² | 0 | Fensterarbeiten | Fensteröffnung | 0 | 3.75 |  | 1155Wa 0000004701 | 0 | - | 0,51 | AllplanAttributes - U-Wert: 0.9; Schallschutzklasse: 32; Sonnenschutztyp: Movable
Fensteröffnung | H2 Ebene +1 | 1155Fen2005796780 | m² | 0 | Fensterarbeiten | Fensteröffnung | 0 | 3.75 | NEW | 1155Wa 0000004705 | 0 | - | 0,51 | AllplanAttributes - U-Wert: 0.9; Schallschutzklasse: 32; Sonnenschutztyp: Movable
Fensteröffnung | H2 Ebene +1 | 1155Fen2005796779 | m² | 0 | Fensterarbeiten | Fensteröffnung | 0 | 3.75 | NEW | 1155Wa 0000004709 | 0 | - | 0,51 | AllplanAttributes - U-Wert: 0.9; Schallschutzklasse: 32; Sonnenschutztyp: Movable
Fensteröffnung | H2 Ebene +1 | 1155Fen2005796778 | m² | 0 | Fensterarbeiten | Fensteröffnung | 0 | 3.75 | NEW | 1155Wa 0000004713 | 0 | - | 0,51 | AllplanAttributes - U-Wert: 0.9; Schallschutzklasse: 32; Sonnenschutztyp: Movable
Fensteröffnung | H2 Ebene +1 | 1155Fen2005786156 | m² | 0 | Fensterarbeiten | Fensteröffnung | 0 | 3.75 |  | 1155Wa 0000004865 | 0 | - | 0,51 | AllplanAttributes - U-Wert: 0.9; Schallschutzklasse: 32; Sonnenschutztyp: Movable
Fensteröffnung | H2 Ebene +1 | 1155Fen2005786072 | m² | 0 | Fensterarbeiten | Fensteröffnung | 0 | 3.75 |  | 1155Wa 0000004865 | 0 | - | 0,51 | AllplanAttributes - U-Wert: 0.9; Schallschutzklasse: 32; Sonnenschutztyp: Movable
Fensteröffnung | H2 Ebene +1 | 1155Fen2005786155 | m³ | 0 | Fensterarbeiten | Fensteröffnung | 0 | 3.75 |  | 1155Wa 0000004860 | 0 | - | 0,51 | AllplanAttributes - U-Wert: 0.9; Schallschutzklasse: 32; Sonnenschutztyp: Movable
Fensteröffnung | H2 Ebene +1 | 1155Fen2005786071 | m³ | 0 | Fensterarbeiten | Fensteröffnung | 0 | 3.75 |  | 1155Wa 0000004860 | 0 | - | 0,51 | AllplanAttributes - U-Wert: 0.9; Schallschutzklasse: 32; Sonnenschutztyp: Movable
Fensteröffnung | H2 Ebene +1 | 1155Fen2005786154 | m³ | 0 | Fensterarbeiten | Fensteröffnung | 0 | 3.75 |  | 1155Wa 0000004855 | 0 | - | 0,51 | AllplanAttributes - U-Wert: 0.9; Schallschutzklasse: 32; Sonnenschutztyp: Movable
Fensteröffnung | H2 Ebene +1 | 1155Fen2005786070 | m³ | 0 | Fensterarbeiten | Fensteröffnung | 0 | 3.75 |  | 1155Wa 0000004855 | 0 | - | 0,51 | AllplanAttributes - U-Wert: 0.9; Schallschutzklasse: 32; Sonnenschutztyp: Movable
Fensteröffnung | H2 Ebene +1 | 1155Fen2005786153 | m² | 0 | Fensterarbeiten | Fensteröffnung | 0 | 3.75 |  | 1155Wa 0000004850 | 0 | - | 0,51 | AllplanAttributes - U-Wert: 0.9; Schallschutzklasse: 32; Sonnenschutztyp: Movable
Fensteröffnung | H2 Ebene +1 | 1155Fen2005786069 | m² | 0 | Fensterarbeiten | Fensteröffnung | 0 | 3.75 |  | 1155Wa 0000004850 | 0 | - | 0,51 | AllplanAttributes - U-Wert: 0.9; Schallschutzklasse: 32; Sonnenschutztyp: Movable
Fensteröffnung | H2 Ebene +1 | 1155Fen2005786152 | m² | 0 | Fensterarbeiten | Fensteröffnung | 0 | 3.75 | NEW | 1155Wa 0000004845 | 0 | - | 0,51 | AllplanAttributes - U-Wert: 0.9; Schallschutzklasse: 32; Sonnenschutztyp: Movable
Fensteröffnung | H2 Ebene +1 | 1155Fen2005786068 | m² | 0 | Fensterarbeiten | Fensteröffnung | 0 | 3.75 | NEW | 1155Wa 0000004845 | 0 | - | 0,51 | AllplanAttributes - U-Wert: 0.9; Schallschutzklasse: 32; Sonnenschutztyp: Movable
Fensteröffnung | H2 Ebene +1 | 1155Fen2005786151 | m² | 0 | Fensterarbeiten | Fensteröffnung | 0 | 3.75 | NEW | 1155Wa 0000004840 | 0 | - | 0,51 | AllplanAttributes - U-Wert: 0.9; Schallschutzklasse: 32; Sonnenschutztyp: Movable
Fensteröffnung | H2 Ebene +1 | 1155Fen2005786067 | m² | 0 | Fensterarbeiten | Fensteröffnung | 0 | 3.75 | NEW | 1155Wa 0000004840 | 0 | - | 0,51 | AllplanAttributes - U-Wert: 0.9; Schallschutzklasse: 32; Sonnenschutztyp: Movable
Fensteröffnung | H2 Ebene +1 | 1155Fen2005786150 | m² | 0 | Fensterarbeiten | Fensteröffnung | 0 | 3.75 | NEW | 1155Wa 0000004835 | 0 | - | 0,51 | AllplanAttributes - U-Wert: 0.9; Schallschutzklasse: 32; Sonnenschutztyp: Movable
Fensteröffnung | H2 Ebene +1 | 1155Fen2005786066 | m² | 0 | Fensterarbeiten | Fensteröffnung | 0 | 3.75 | NEW | 1155Wa 0000004835 | 0 | - | 0,51 | AllplanAttributes - U-Wert: 0.9; Schallschutzklasse: 32; Sonnenschutztyp: Movable
Fensteröffnung | H2 Ebene +1 | 1155Fen0000173514 | m² | 0 | Fensterarbeiten | Fensteröffnung | 0 | 3.75 |  | 1155Wa 0000004893 | 0 | - | 0,51 | AllplanAttributes - U-Wert: 0.9; Schallschutzklasse: 32; Sonnenschutztyp: Movable
Fensteröffnung | H2 Ebene +1 | 1155Fen0000173527 | m³ | 0 | Fensterarbeiten | Fensteröffnung | 0 | 3.75 |  | 1155Wa 0000004889 | 0 | - | 0,51 | AllplanAttributes - U-Wert: 0.9; Schallschutzklasse: 32; Sonnenschutztyp: Movable
Fensteröffnung | H2 Ebene +1 | 1155Fen0000173525 | m³ | 0 | Fensterarbeiten | Fensteröffnung | 0 | 3.75 |  | 1155Wa 0000004885 | 0 | - | 0,51 | AllplanAttributes - U-Wert: 0.9; Schallschutzklasse: 32; Sonnenschutztyp: Movable
Fensteröffnung | H2 Ebene +1 | 1155Fen0000173523 | m² | 0 | Fensterarbeiten | Fensteröffnung | 0 | 3.75 |  | 1155Wa 0000004881 | 0 | - | 0,51 | AllplanAttributes - U-Wert: 0.9; Schallschutzklasse: 32; Sonnenschutztyp: Movable
Fensteröffnung | H2 Ebene +1 | 1155Fen0000173521 | m² | 0 | Fensterarbeiten | Fensteröffnung | 0 | 3.75 | NEW | 1155Wa 0000004877 | 0 | - | 0,51 | AllplanAttributes - U-Wert: 0.9; Schallschutzklasse: 32; Sonnenschutztyp: Movable
Fensteröffnung | H2 Ebene +1 | 1155Fen0000173519 | m² | 0 | Fensterarbeiten | Fensteröffnung | 0 | 3.75 | NEW | 1155Wa 0000004873 | 0 | - | 0,51 | AllplanAttributes - U-Wert: 0.9; Schallschutzklasse: 32; Sonnenschutztyp: Movable
Fensteröffnung | H2 Ebene +1 | 1155Fen0000173517 | m² | 0 | Fensterarbeiten | Fensteröffnung | 0 | 3.75 | NEW | 1155Wa 0000004869 | 0 | - | 0,51 | AllplanAttributes - ash D_Detailverweis: FSLH2; ash D_Plannummer: D833; U-Wert: 0.9; Schallschutzklasse: 32; Sonnenschutztyp: Movable
Fensteröffnung | H2 Ebene +1 | 1155Fen0000005560 | m² | 0 | Fensterarbeiten | Fensteröffnung | 0 | 3.75 |  | 1155Wa 0000005133 | 0 | - | 0,51 | AllplanAttributes - U-Wert: 0.9; Schallschutzklasse: 32; Sonnenschutztyp: Movable
Fensteröffnung | H2 Ebene +1 | 1155Fen0000005563 | m² | 0 | Fensterarbeiten | Fensteröffnung | 0 | 3.75 |  | 1155Wa 0000005133 | 0 | - | 0,51 | AllplanAttributes - U-Wert: 0.9; Schallschutzklasse: 32; Sonnenschutztyp: Movable
Fensteröffnung | H2 Ebene +1 | 1155Fen0000005569 | m² | 0 | Fensterarbeiten | Fensteröffnung | 0 | 3.75 |  | 1155Wa 0000005133 | 0 | - | 0,51 | AllplanAttributes - U-Wert: 0.9; Schallschutzklasse: 32; Sonnenschutztyp: Movable
Fensteröffnung | H2 Ebene +1 | 1155Fen0000005572 | m² | 0 | Fensterarbeiten | Fensteröffnung | 0 | 3.75 |  | 1155Wa 0000005133 | 0 | - | 0,51 | AllplanAttributes - U-Wert: 0.9; Schallschutzklasse: 32; Sonnenschutztyp: Movable
Fensteröffnung | H2 Ebene +1 | 1155Fen0000005557 | m² | 0 | Fensterarbeiten | Fensteröffnung | 0 | 3.75 |  | 1155Wa 0000005133 | 0 | - | 0,51 | AllplanAttributes - U-Wert: 0.9; Schallschutzklasse: 32; Sonnenschutztyp: Movable
Fensteröffnung | H2 Ebene +1 | 1155Fen2005808101 | m² | 0 | Fensterarbeiten | Fensteröffnung | 0 | 3.75 |  | 1155Wa 0000005133 | 0 | - | 0,51 | AllplanAttributes - U-Wert: 0.9; Schallschutzklasse: 32; Sonnenschutztyp: Movable
Fensteröffnung | H2 Ebene +1 | 1155Fen0000003431 | m³ | 0 | Fensterarbeiten | Fensteröffnung | 0 | 3.75 |  | 1155Wa 0000005124 | 0 | - | 0,51 | AllplanAttributes - U-Wert: 0.9; Schallschutzklasse: 32; Sonnenschutztyp: Movable
Fensteröffnung | H2 Ebene +1 | 1155Fen0000003435 | m³ | 0 | Fensterarbeiten | Fensteröffnung | 0 | 3.75 |  | 1155Wa 0000005124 | 0 | - | 0,51 | AllplanAttributes - U-Wert: 0.9; Schallschutzklasse: 32; Sonnenschutztyp: Movable
Fensteröffnung | H2 Ebene +1 | 1155Fen0000003443 | m³ | 0 | Fensterarbeiten | Fensteröffnung | 0 | 3.75 |  | 1155Wa 0000005124 | 0 | - | 0,51 | AllplanAttributes - U-Wert: 0.9; Schallschutzklasse: 32; Sonnenschutztyp: Movable
Fensteröffnung | H2 Ebene +1 | 1155Fen0000003447 | m³ | 0 | Fensterarbeiten | Fensteröffnung | 0 | 3.75 |  | 1155Wa 0000005124 | 0 | - | 0,51 | AllplanAttributes - U-Wert: 0.9; Schallschutzklasse: 32; Sonnenschutztyp: Movable
Fensteröffnung | H2 Ebene +1 | 1155Fen0000003427 | m³ | 0 | Fensterarbeiten | Fensteröffnung | 0 | 3.75 |  | 1155Wa 0000005124 | 0 | - | 0,51 | AllplanAttributes - U-Wert: 0.9; Schallschutzklasse: 32; Sonnenschutztyp: Movable
Fensteröffnung | H2 Ebene +1 | 1155Fen2005808095 | m³ | 0 | Fensterarbeiten | Fensteröffnung | 0 | 3.75 |  | 1155Wa 0000005124 | 0 | - | 0,51 | AllplanAttributes - U-Wert: 0.9; Schallschutzklasse: 32; Sonnenschutztyp: Movable
Fensteröffnung | H2 Ebene +1 | 1155Fen0000003433 | m³ | 0 | Fensterarbeiten | Fensteröffnung | 0 | 3.75 |  | 1155Wa 0000005115 | 0 | - | 0,51 | AllplanAttributes - U-Wert: 0.9; Schallschutzklasse: 32; Sonnenschutztyp: Movable
Fensteröffnung | H2 Ebene +1 | 1155Fen0000003437 | m³ | 0 | Fensterarbeiten | Fensteröffnung | 0 | 3.75 |  | 1155Wa 0000005115 | 0 | - | 0,51 | AllplanAttributes - U-Wert: 0.9; Schallschutzklasse: 32; Sonnenschutztyp: Movable
Fensteröffnung | H2 Ebene +1 | 1155Fen0000003445 | m³ | 0 | Fensterarbeiten | Fensteröffnung | 0 | 3.75 |  | 1155Wa 0000005115 | 0 | - | 0,51 | AllplanAttributes - U-Wert: 0.9; Schallschutzklasse: 32; Sonnenschutztyp: Movable
Fensteröffnung | H2 Ebene +1 | 1155Fen0000003449 | m³ | 0 | Fensterarbeiten | Fensteröffnung | 0 | 3.75 |  | 1155Wa 0000005115 | 0 | - | 0,51 | AllplanAttributes - U-Wert: 0.9; Schallschutzklasse: 32; Sonnenschutztyp: Movable
Fensteröffnung | H2 Ebene +1 | 1155Fen0000003429 | m³ | 0 | Fensterarbeiten | Fensteröffnung | 0 | 3.75 |  | 1155Wa 0000005115 | 0 | - | 0,51 | AllplanAttributes - U-Wert: 0.9; Schallschutzklasse: 32; Sonnenschutztyp: Movable
Fensteröffnung | H2 Ebene +1 | 1155Fen2005808096 | m³ | 0 | Fensterarbeiten | Fensteröffnung | 0 | 3.75 |  | 1155Wa 0000005115 | 0 | - | 0,51 | AllplanAttributes - U-Wert: 0.9; Schallschutzklasse: 32; Sonnenschutztyp: Movable
Fensteröffnung | H2 Ebene +1 | 1155Fen0000003387 | m² | 0 | Fensterarbeiten | Fensteröffnung | 0 | 3.75 |  | 1155Wa 0000005106 | 0 | - | 0,51 | AllplanAttributes - U-Wert: 0.9; Schallschutzklasse: 32; Sonnenschutztyp: Movable
Fensteröffnung | H2 Ebene +1 | 1155Fen0000003395 | m² | 0 | Fensterarbeiten | Fensteröffnung | 0 | 3.75 |  | 1155Wa 0000005106 | 0 | - | 0,51 | AllplanAttributes - U-Wert: 0.9; Schallschutzklasse: 32; Sonnenschutztyp: Movable
Fensteröffnung | H2 Ebene +1 | 1155Fen0000003411 | m² | 0 | Fensterarbeiten | Fensteröffnung | 0 | 3.75 |  | 1155Wa 0000005106 | 0 | - | 0,51 | AllplanAttributes - U-Wert: 0.9; Schallschutzklasse: 32; Sonnenschutztyp: Movable
Fensteröffnung | H2 Ebene +1 | 1155Fen0000003419 | m² | 0 | Fensterarbeiten | Fensteröffnung | 0 | 3.75 |  | 1155Wa 0000005106 | 0 | - | 0,51 | AllplanAttributes - U-Wert: 0.9; Schallschutzklasse: 32; Sonnenschutztyp: Movable
Fensteröffnung | H2 Ebene +1 | 1155Fen0000003379 | m² | 0 | Fensterarbeiten | Fensteröffnung | 0 | 3.75 |  | 1155Wa 0000005106 | 0 | - | 0,51 | AllplanAttributes - U-Wert: 0.9; Schallschutzklasse: 32; Sonnenschutztyp: Movable
Fensteröffnung | H2 Ebene +1 | 1155Fen2005808097 | m² | 0 | Fensterarbeiten | Fensteröffnung | 0 | 3.75 |  | 1155Wa 0000005106 | 0 | - | 0,51 | AllplanAttributes - U-Wert: 0.9; Schallschutzklasse: 32; Sonnenschutztyp: Movable
Fensteröffnung | H2 Ebene +1 | 1155Fen0000003389 | m² | 0 | Fensterarbeiten | Fensteröffnung | 0 | 3.75 | NEW | 1155Wa 0000005097 | 0 | - | 0,51 | AllplanAttributes - U-Wert: 0.9; Schallschutzklasse: 32; Sonnenschutztyp: Movable
Fensteröffnung | H2 Ebene +1 | 1155Fen0000003397 | m² | 0 | Fensterarbeiten | Fensteröffnung | 0 | 3.75 | NEW | 1155Wa 0000005097 | 0 | - | 0,51 | AllplanAttributes - U-Wert: 0.9; Schallschutzklasse: 32; Sonnenschutztyp: Movable
Fensteröffnung | H2 Ebene +1 | 1155Fen0000003413 | m² | 0 | Fensterarbeiten | Fensteröffnung | 0 | 3.75 | NEW | 1155Wa 0000005097 | 0 | - | 0,51 | AllplanAttributes - U-Wert: 0.9; Schallschutzklasse: 32; Sonnenschutztyp: Movable
Fensteröffnung | H2 Ebene +1 | 1155Fen0000003421 | m² | 0 | Fensterarbeiten | Fensteröffnung | 0 | 3.75 | NEW | 1155Wa 0000005097 | 0 | - | 0,51 | AllplanAttributes - U-Wert: 0.9; Schallschutzklasse: 32; Sonnenschutztyp: Movable
Fensteröffnung | H2 Ebene +1 | 1155Fen0000003381 | m² | 0 | Fensterarbeiten | Fensteröffnung | 0 | 3.75 | NEW | 1155Wa 0000005097 | 0 | - | 0,51 | AllplanAttributes - U-Wert: 0.9; Schallschutzklasse: 32; Sonnenschutztyp: Movable
Fensteröffnung | H2 Ebene +1 | 1155Fen2005808098 | m² | 0 | Fensterarbeiten | Fensteröffnung | 0 | 3.75 | NEW | 1155Wa 0000005097 | 0 | - | 0,51 | AllplanAttributes - U-Wert: 0.9; Schallschutzklasse: 32; Sonnenschutztyp: Movable
Fensteröffnung | H2 Ebene +1 | 1155Fen0000003391 | m² | 0 | Fensterarbeiten | Fensteröffnung | 0 | 3.75 | NEW | 1155Wa 0000005088 | 0 | - | 0,51 | AllplanAttributes - U-Wert: 0.9; Schallschutzklasse: 32; Sonnenschutztyp: Movable
Fensteröffnung | H2 Ebene +1 | 1155Fen0000003399 | m² | 0 | Fensterarbeiten | Fensteröffnung | 0 | 3.75 | NEW | 1155Wa 0000005088 | 0 | - | 0,51 | AllplanAttributes - U-Wert: 0.9; Schallschutzklasse: 32; Sonnenschutztyp: Movable
Fensteröffnung | H2 Ebene +1 | 1155Fen0000003415 | m² | 0 | Fensterarbeiten | Fensteröffnung | 0 | 3.75 | NEW | 1155Wa 0000005088 | 0 | - | 0,51 | AllplanAttributes - U-Wert: 0.9; Schallschutzklasse: 32; Sonnenschutztyp: Movable
Fensteröffnung | H2 Ebene +1 | 1155Fen0000003423 | m² | 0 | Fensterarbeiten | Fensteröffnung | 0 | 3.75 | NEW | 1155Wa 0000005088 | 0 | - | 0,51 | AllplanAttributes - U-Wert: 0.9; Schallschutzklasse: 32; Sonnenschutztyp: Movable
Fensteröffnung | H2 Ebene +1 | 1155Fen0000003383 | m² | 0 | Fensterarbeiten | Fensteröffnung | 0 | 3.75 | NEW | 1155Wa 0000005088 | 0 | - | 0,51 | AllplanAttributes - U-Wert: 0.9; Schallschutzklasse: 32; Sonnenschutztyp: Movable
Fensteröffnung | H2 Ebene +1 | 1155Fen2005808099 | m² | 0 | Fensterarbeiten | Fensteröffnung | 0 | 3.75 | NEW | 1155Wa 0000005088 | 0 | - | 0,51 | AllplanAttributes - U-Wert: 0.9; Schallschutzklasse: 32; Sonnenschutztyp: Movable
Fensteröffnung | H2 Ebene +1 | 1155Fen0000003393 | m² | 0 | Fensterarbeiten | Fensteröffnung | 0 | 3.75 | NEW | 1155Wa 0000005079 | 0 | - | 0,51 | AllplanAttributes - U-Wert: 0.9; Schallschutzklasse: 32; Sonnenschutztyp: Movable
Fensteröffnung | H2 Ebene +1 | 1155Fen0000003401 | m² | 0 | Fensterarbeiten | Fensteröffnung | 0 | 3.75 | NEW | 1155Wa 0000005079 | 0 | - | 0,51 | AllplanAttributes - U-Wert: 0.9; Schallschutzklasse: 32; Sonnenschutztyp: Movable
Fensteröffnung | H2 Ebene +1 | 1155Fen0000003417 | m² | 0 | Fensterarbeiten | Fensteröffnung | 0 | 3.75 | NEW | 1155Wa 0000005079 | 0 | - | 0,51 | AllplanAttributes - U-Wert: 0.9; Schallschutzklasse: 32; Sonnenschutztyp: Movable
Fensteröffnung | H2 Ebene +1 | 1155Fen0000003425 | m² | 0 | Fensterarbeiten | Fensteröffnung | 0 | 3.75 | NEW | 1155Wa 0000005079 | 0 | - | 0,51 | AllplanAttributes - U-Wert: 0.9; Schallschutzklasse: 32; Sonnenschutztyp: Movable
Fensteröffnung | H2 Ebene +1 | 1155Fen0000003385 | m² | 0 | Fensterarbeiten | Fensteröffnung | 0 | 3.75 | NEW | 1155Wa 0000005079 | 0 | - | 0,51 | AllplanAttributes - U-Wert: 0.9; Schallschutzklasse: 32; Sonnenschutztyp: Movable
Fensteröffnung | H2 Ebene +1 | 1155Fen2005808100 | m² | 0 | Fensterarbeiten | Fensteröffnung | 0 | 3.75 | NEW | 1155Wa 0000005079 | 0 | - | 0,51 | AllplanAttributes - U-Wert: 0.9; Schallschutzklasse: 32; Sonnenschutztyp: Movable
Fensteröffnung | H2 Ebene +1 | 1155Fen0000010223 | m² |  | Fensterarbeiten | Fensteröffnung |  | 3.75 |  | 1155Wa 0000002335 | 0 | - | 0,51 | AllplanAttributes - U-Wert: 0.9; Schallschutzklasse: 32; Sonnenschutztyp: Movable
Fensteröffnung | H2 Ebene +1 | 1155Fen0000010215 | m³ | 0 | Fensterarbeiten | Fensteröffnung | 0 | 3.75 |  | 1155Wa 0000002341 | 0 | - | 0,51 | AllplanAttributes - U-Wert: 0.9; Schallschutzklasse: 32; Sonnenschutztyp: Movable
Fensteröffnung | H2 Ebene +1 | 1155Fen0000010217 | m² | 0 | Fensterarbeiten | Fensteröffnung | 0 | 3.75 | NEW | 1155Wa 0000002347 | 0 | - | 0,51 | AllplanAttributes - U-Wert: 0.9; Schallschutzklasse: 32; Sonnenschutztyp: Movable
Fensteröffnung | H2 Ebene +1 | 1155Fen0000010219 | m² | 0 | Fensterarbeiten | Fensteröffnung | 0 | 3.75 | NEW | 1155Wa 0000002353 | 0 | - | 0,51 | AllplanAttributes - U-Wert: 0.9; Schallschutzklasse: 32; Sonnenschutztyp: Movable
Fensteröffnung | H2 Ebene +1 | 1155Fen0000010221 | m² | 0 | Fensterarbeiten | Fensteröffnung | 0 | 3.75 | NEW | 1155Wa 0000002359 | 0 | - | 0,51 | AllplanAttributes - U-Wert: 0.9; Schallschutzklasse: 32; Sonnenschutztyp: Movable
Fensteröffnung | H2 Ebene +1 | 1155Fen0000081291 | m² | 0 | Fensterarbeiten | Fensteröffnung | 0 |  | NEW | 1155Wa 0000081159 | 0 | - | 0,51 | AllplanAttributes - ash D_Detailverweis: FS TR; ash D_Plannummer: D1530; U-Wert: 0.9; Schallschutzklasse: 32; Sonnenschutztyp: Movable
Fensteröffnung | H2 Ebene +1 | 1155Fen0000010229 | m² |  | Wärmedämm-Verbundsysteme | Fensteröffnung |  | 3.75 | NEW | 1155Wa 0000003016 | 0 | - | 0,51 | AllplanAttributes - Material: Fensterelement; Tragendes Bauteil: no; Brandabschnittsdefinierendes Bauteil: no; U-Wert: 0.9; Schallschutzklasse: 32; Sonnenschutztyp: Movable
Fensteröffnung | H2 Ebene +1 | 1155Fen0000010237 | m³ | 0 | Wärmedämm-Verbundsysteme | Fensteröffnung | 0 | 3.75 | NEW | 1155Wa 0000002967 | 0 | - | 0,51 | AllplanAttributes - Material: Fensterelement; Außenliegend: yes; U-Wert: 0.9; Schallschutzklasse: 32; Sonnenschutztyp: Movable
Fensteröffnung | H2 Ebene +1 | 1155Fen0000010235 | m² | 0 | Wärmedämm-Verbundsysteme | Fensteröffnung | 0 | 3.75 | NEW | 1155Wa 0000002971 | 0 | - | 0,51 | AllplanAttributes - U-Wert: 0.9; Schallschutzklasse: 32; Sonnenschutztyp: Movable
Fensteröffnung | H2 Ebene +1 | 1155Fen0000010233 | m² | 0 | Wärmedämm-Verbundsysteme | Fensteröffnung | 0 | 3.75 | NEW | 1155Wa 0000002975 | 0 | - | 0,51 | AllplanAttributes - U-Wert: 0.9; Schallschutzklasse: 32; Sonnenschutztyp: Movable
Fensteröffnung | H2 Ebene +1 | 1155Fen0000010231 | m² | 0 | Wärmedämm-Verbundsysteme | Fensteröffnung | 0 | 3.75 | NEW | 1155Wa 0000002979 | 0 | - | 0,51 | AllplanAttributes - U-Wert: 0.9; Schallschutzklasse: 32; Sonnenschutztyp: Movable
Fensteröffnung | H2 Ebene +1 | 1155Fen0000082764 | m² | 0 | Wärmedämm-Verbundsysteme | Fensteröffnung | 0 |  | NEW | 1155Wa 0000082689 | 0 | - | 0,51 | AllplanAttributes - U-Wert: 0.9; Schallschutzklasse: 32; Sonnenschutztyp: Movable
2 x Fensteröffnung | H2 Ebene +1 | 1155Fen0000086106 | m³ | 0 | Wärmedämm-Verbundsysteme | Fensteröffnung | 0 | 3.75 | NEW | 1155Wa 0000086112 | 0 | - | 0,51 | AllplanAttributes - Material: Fensterelement; Außenliegend: yes; U-Wert: 0.9; Schallschutzklasse: 32; Sonnenschutztyp: Movable
Fensteröffnung | H2 Ebene +1 | 1155Fen0000086107 | m² |  | Wärmedämm-Verbundsysteme | Fensteröffnung |  | 3.75 | NEW | 1155Wa 0000086111 | 0 | - | 0,51 | AllplanAttributes - Material: Fensterelement; Tragendes Bauteil: no; Brandabschnittsdefinierendes Bauteil: no; U-Wert: 0.9; Schallschutzklasse: 32; Sonnenschutztyp: Movable
2 x Fensteröffnung | H2 Ebene +1 | 1155Fen0000086105 | m³ | 0 | Wärmedämm-Verbundsysteme | Fensteröffnung | 0 | 3.75 | NEW | 1155Wa 0000086113 | 0 | - | 0,51 | AllplanAttributes - U-Wert: 0.9; Schallschutzklasse: 32; Sonnenschutztyp: Movable
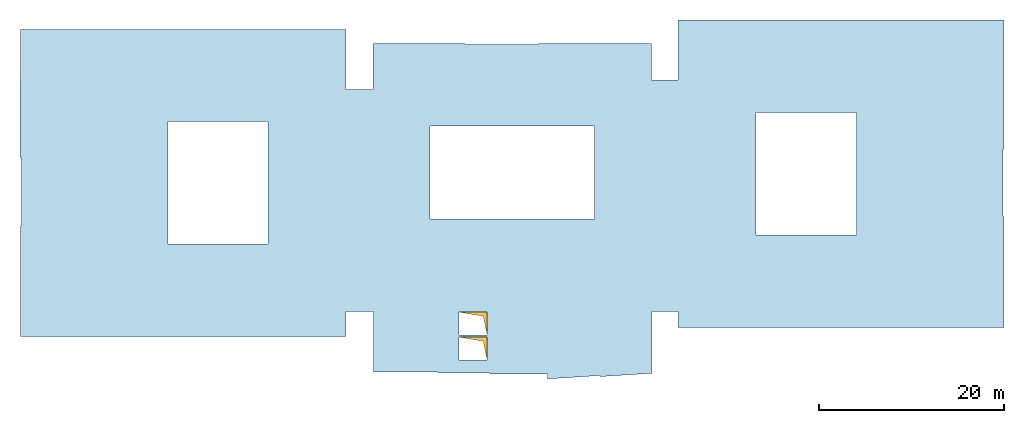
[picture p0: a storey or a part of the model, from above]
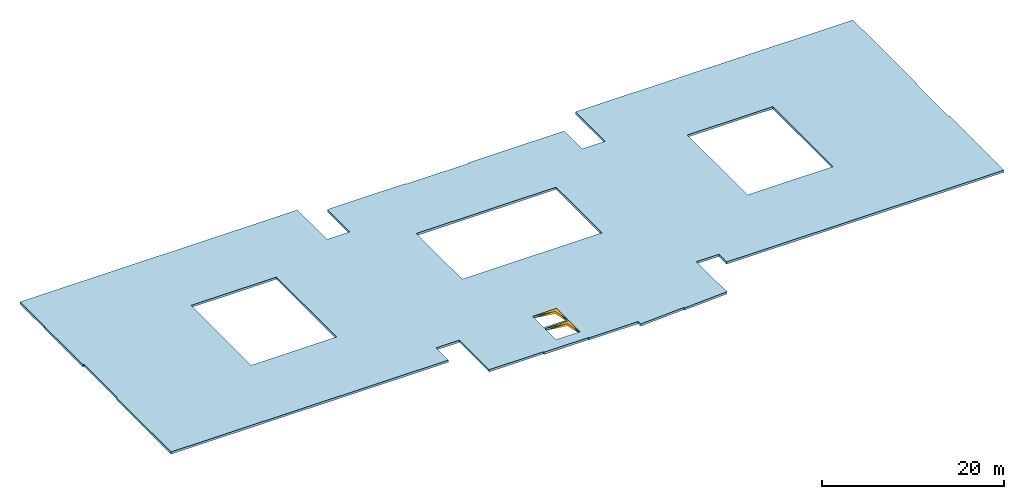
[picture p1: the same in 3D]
Properties of the parts of a building model (IFC4), part 36 of 80

# IfcOpeningElement: Opening (3497)
Name | In | Allright_Bauteil_ID | Abrechnungsart | Versatz_oben | Gewerk | Objektname | Versatz_unten | OKFF | Status | P_ID | AllplanAttributes, Feuerwiderstandsklasse | Sicherheitsklasse | g-Wert
2 x Fensteröffnung | H2 Ebene +1 | 1155Fen0000086104 | m² | 0 | Wärmedämm-Verbundsysteme | Fensteröffnung | 0 | 3.75 | NEW | 1155Wa 0000086114 | 0 | - | 0,51 | AllplanAttributes - U-Wert: 0.9; Schallschutzklasse: 32; Sonnenschutztyp: Movable
2 x Fensteröffnung | H2 Ebene +1 | 1155Fen0000086103 | m² | 0 | Wärmedämm-Verbundsysteme | Fensteröffnung | 0 | 3.75 | NEW | 1155Wa 0000086115 | 0 | - | 0,51 | AllplanAttributes - U-Wert: 0.9; Schallschutzklasse: 32; Sonnenschutztyp: Movable
2 x Fensteröffnung | H2 Ebene +1 | 1155Fen0000086102 | m² | 0 | Wärmedämm-Verbundsysteme | Fensteröffnung | 0 | 3.75 | NEW | 1155Wa 0000086116 | 0 | - | 0,51 | AllplanAttributes - U-Wert: 0.9; Schallschutzklasse: 32; Sonnenschutztyp: Movable
2 x Fensteröffnung | H2 Ebene +1 | 1155Fen0000086101 | m² | 0 | Wärmedämm-Verbundsysteme | Fensteröffnung | 0 | 3.75 | NEW | 1155Wa 0000086117 | 0 | - | 0,51 | AllplanAttributes - U-Wert: 0.9; Schallschutzklasse: 32; Sonnenschutztyp: Movable
Türöffnung | H2 Ebene +1 | 1155Tür0000238076 | m² |  | Zimmer- und Holzbauarbeiten | Türöffnung |  | 3.75 | NEW | 1155Wa 0000010295 | 0 | - | 0,51 | AllplanAttributes - U-Wert: 0.9; Schallschutzklasse: 32; Sonnenschutztyp: Movable; Türanschlag: DIN R
Fensteröffnung | H2 Ebene +1 | 1155Fen0813745892 | m² |  | Wärmedämm-Verbundsysteme | Fensteröffnung |  | 3.75 | NEW | 1155Wa 0000192475 | 0 | - | 0,51 | AllplanAttributes - Material: Fensterelement; Tragendes Bauteil: no; Brandabschnittsdefinierendes Bauteil: no; U-Wert: 0.9; Schallschutzklasse: 35; Sonnenschutztyp: Movable
Fensteröffnung | H2 Ebene +1 | 1155Fen0813745890 | m² |  | Wärmedämm-Verbundsysteme | Fensteröffnung |  | 3.75 | NEW | 1155Wa 0000192475 | 0 | - | 0,51 | AllplanAttributes - Material: Fensterelement; Tragendes Bauteil: no; Brandabschnittsdefinierendes Bauteil: no; U-Wert: 0.9; Schallschutzklasse: 35; Sonnenschutztyp: Movable
Fensteröffnung | H2 Ebene +1 | 1155Fen0813745887 | m³ | 0 | Wärmedämm-Verbundsysteme | Fensteröffnung | 0 | 3.75 | NEW | 1155Wa 0000192476 | 0 | - | 0,51 | AllplanAttributes - Material: Fensterelement; Außenliegend: yes; U-Wert: 0.9; Schallschutzklasse: 35; Sonnenschutztyp: Movable
Fensteröffnung | H2 Ebene +1 | 1155Fen0813745882 | m³ | 0 | Wärmedämm-Verbundsysteme | Fensteröffnung | 0 | 3.75 | NEW | 1155Wa 0000192476 | 0 | - | 0,51 | AllplanAttributes - Material: Fensterelement; Außenliegend: yes; U-Wert: 0.9; Schallschutzklasse: 35; Sonnenschutztyp: Movable
Fensteröffnung | H2 Ebene +1 | 1155Fen0813745884 | m³ | 0 | Wärmedämm-Verbundsysteme | Fensteröffnung | 0 | 3.75 | NEW | 1155Wa 0000192477 | 0 | - | 0,51 | AllplanAttributes - U-Wert: 0.9; Schallschutzklasse: 35; Sonnenschutztyp: Movable
Fensteröffnung | H2 Ebene +1 | 1155Fen0813745880 | m³ | 0 | Wärmedämm-Verbundsysteme | Fensteröffnung | 0 | 3.75 | NEW | 1155Wa 0000192477 | 0 | - | 0,51 | AllplanAttributes - U-Wert: 0.9; Schallschutzklasse: 35; Sonnenschutztyp: Movable
Fensteröffnung | H2 Ebene +1 | 1155Fen0813745888 | m² | 0 | Wärmedämm-Verbundsysteme | Fensteröffnung | 0 | 3.75 | NEW | 1155Wa 0000192478 | 0 | - | 0,51 | AllplanAttributes - U-Wert: 0.9; Schallschutzklasse: 35; Sonnenschutztyp: Movable
Fensteröffnung | H2 Ebene +1 | 1155Fen0813745883 | m² | 0 | Wärmedämm-Verbundsysteme | Fensteröffnung | 0 | 3.75 | NEW | 1155Wa 0000192478 | 0 | - | 0,51 | AllplanAttributes - U-Wert: 0.9; Schallschutzklasse: 35; Sonnenschutztyp: Movable
Fensteröffnung | H2 Ebene +1 | 1155Fen0813745886 | m² | 0 | Wärmedämm-Verbundsysteme | Fensteröffnung | 0 | 3.75 | NEW | 1155Wa 0000192479 | 0 | - | 0,51 | AllplanAttributes - U-Wert: 0.9; Schallschutzklasse: 35; Sonnenschutztyp: Movable
Fensteröffnung | H2 Ebene +1 | 1155Fen0813745878 | m² | 0 | Wärmedämm-Verbundsysteme | Fensteröffnung | 0 | 3.75 | NEW | 1155Wa 0000192479 | 0 | - | 0,51 | AllplanAttributes - U-Wert: 0.9; Schallschutzklasse: 35; Sonnenschutztyp: Movable
Fensteröffnung | H2 Ebene +1 | 1155Fen0813745889 | m² | 0 | Wärmedämm-Verbundsysteme | Fensteröffnung | 0 | 3.75 | NEW | 1155Wa 0000192480 | 0 | - | 0,51 | AllplanAttributes - U-Wert: 0.9; Schallschutzklasse: 35; Sonnenschutztyp: Movable
Fensteröffnung | H2 Ebene +1 | 1155Fen0813745881 | m² | 0 | Wärmedämm-Verbundsysteme | Fensteröffnung | 0 | 3.75 | NEW | 1155Wa 0000192480 | 0 | - | 0,51 | AllplanAttributes - U-Wert: 0.9; Schallschutzklasse: 35; Sonnenschutztyp: Movable
Fensteröffnung | H2 Ebene +1 | 1155Fen0813745885 | m² | 0 | Wärmedämm-Verbundsysteme | Fensteröffnung | 0 | 3.75 | NEW | 1155Wa 0000192481 | 0 | - | 0,51 | AllplanAttributes - U-Wert: 0.9; Schallschutzklasse: 35; Sonnenschutztyp: Movable
Fensteröffnung | H2 Ebene +1 | 1155Fen0813745879 | m² | 0 | Wärmedämm-Verbundsysteme | Fensteröffnung | 0 | 3.75 | NEW | 1155Wa 0000192481 | 0 | - | 0,51 | AllplanAttributes - U-Wert: 0.9; Schallschutzklasse: 35; Sonnenschutztyp: Movable
Fensteröffnung | H2 Ebene +1 | 1155Fen0000200041 | m² |  | Fensterarbeiten | Fensteröffnung |  | 3.75 |  | 1155Wa 0000200048 | 0 | - | 0,51 | AllplanAttributes - U-Wert: 0.9; Schallschutzklasse: 32; Sonnenschutztyp: Movable
Fensteröffnung | H2 Ebene +1 | 1155Fen0000200034 | m² |  | Fensterarbeiten | Fensteröffnung |  | 3.75 |  | 1155Wa 0000200048 | 0 | - | 0,51 | AllplanAttributes - U-Wert: 0.9; Schallschutzklasse: 32; Sonnenschutztyp: Movable
Fensteröffnung | H2 Ebene +1 | 1155Fen0000200033 | m³ | 0 | Fensterarbeiten | Fensteröffnung | 0 | 3.75 |  | 1155Wa 0000200047 | 0 | - | 0,51 | AllplanAttributes - U-Wert: 0.9; Schallschutzklasse: 32; Sonnenschutztyp: Movable
2 x Fensteröffnung | H2 Ebene +1 | 1155Fen0000200040 | m³ | 0 | Fensterarbeiten | Fensteröffnung | 0 | 3.75 |  | 1155Wa 0000200047 | 0 | - | 0,51 | AllplanAttributes - U-Wert: 0.9; Schallschutzklasse: 32; Sonnenschutztyp: Movable
2 x Fensteröffnung | H2 Ebene +1 | 1155Fen0000200032 | m² | 0 | Fensterarbeiten | Fensteröffnung | 0 | 3.75 |  | 1155Wa 0000200046 | 0 | - | 0,51 | AllplanAttributes - U-Wert: 0.9; Schallschutzklasse: 32; Sonnenschutztyp: Movable
2 x Fensteröffnung | H2 Ebene +1 | 1155Fen0000200039 | m² | 0 | Fensterarbeiten | Fensteröffnung | 0 | 3.75 |  | 1155Wa 0000200046 | 0 | - | 0,51 | AllplanAttributes - U-Wert: 0.9; Schallschutzklasse: 32; Sonnenschutztyp: Movable
Fensteröffnung | H2 Ebene +1 | 1155Fen0000200031 | m² | 0 | Fensterarbeiten | Fensteröffnung | 0 | 3.75 |  | 1155Wa 0000200045 | 0 | - | 0,51 | AllplanAttributes - U-Wert: 0.9; Schallschutzklasse: 32; Sonnenschutztyp: Movable
Fensteröffnung | H2 Ebene +1 | 1155Fen0000200038 | m² | 0 | Fensterarbeiten | Fensteröffnung | 0 | 3.75 |  | 1155Wa 0000200045 | 0 | - | 0,51 | AllplanAttributes - U-Wert: 0.9; Schallschutzklasse: 32; Sonnenschutztyp: Movable
Fensteröffnung | H2 Ebene +1 | 1155Fen0000200030 | m² | 0 | Fensterarbeiten | Fensteröffnung | 0 | 3.75 | NEW | 1155Wa 0000200044 | 0 | - | 0,51 | AllplanAttributes - U-Wert: 0.9; Schallschutzklasse: 32; Sonnenschutztyp: Movable
Fensteröffnung | H2 Ebene +1 | 1155Fen0000200037 | m² | 0 | Fensterarbeiten | Fensteröffnung | 0 | 3.75 | NEW | 1155Wa 0000200044 | 0 | - | 0,51 | AllplanAttributes - U-Wert: 0.9; Schallschutzklasse: 32; Sonnenschutztyp: Movable
Fensteröffnung | H2 Ebene +1 | 1155Fen0000200036 | m² | 0 | Fensterarbeiten | Fensteröffnung | 0 | 3.75 | NEW | 1155Wa 0000200043 | 0 | - | 0,51 | AllplanAttributes - U-Wert: 0.9; Schallschutzklasse: 32; Sonnenschutztyp: Movable
Fensteröffnung | H2 Ebene +1 | 1155Fen0000200029 | m² | 0 | Fensterarbeiten | Fensteröffnung | 0 | 3.75 | NEW | 1155Wa 0000200043 | 0 | - | 0,51 | AllplanAttributes - U-Wert: 0.9; Schallschutzklasse: 32; Sonnenschutztyp: Movable
Fensteröffnung | H2 Ebene +1 | 1155Fen0000200028 | m² | 0 | Fensterarbeiten | Fensteröffnung | 0 | 3.75 | NEW | 1155Wa 0000200042 | 0 | - | 0,51 | AllplanAttributes - U-Wert: 0.9; Schallschutzklasse: 32; Sonnenschutztyp: Movable
Fensteröffnung | H2 Ebene +1 | 1155Fen0000200035 | m² | 0 | Fensterarbeiten | Fensteröffnung | 0 | 3.75 | NEW | 1155Wa 0000200042 | 0 | - | 0,51 | AllplanAttributes - U-Wert: 0.9; Schallschutzklasse: 32; Sonnenschutztyp: Movable
Fensteröffnung | H2 Ebene +1 | 1155Fen0813749774 | m² |  | Fensterarbeiten | Fensteröffnung |  | 3.75 |  | 1155Wa 0000197421 | 0 | - | 0,51 | AllplanAttributes - U-Wert: 0.9; Schallschutzklasse: 32; Sonnenschutztyp: Movable
Fensteröffnung | H2 Ebene +1 | 1155Fen0813749772 | m² |  | Fensterarbeiten | Fensteröffnung |  | 3.75 |  | 1155Wa 0000197421 | 0 | - | 0,51 | AllplanAttributes - U-Wert: 0.9; Schallschutzklasse: 32; Sonnenschutztyp: Movable
Fensteröffnung | H2 Ebene +1 | 1155Fen0813749770 | m² |  | Fensterarbeiten | Fensteröffnung |  | 3.75 |  | 1155Wa 0000197421 | 0 | - | 0,51 | AllplanAttributes - U-Wert: 0.9; Schallschutzklasse: 32; Sonnenschutztyp: Movable
Fensteröffnung | H2 Ebene +1 | 1155Fen0813749768 | m² |  | Fensterarbeiten | Fensteröffnung |  | 3.75 |  | 1155Wa 0000197421 | 0 | - | 0,51 | AllplanAttributes - U-Wert: 0.9; Schallschutzklasse: 32; Sonnenschutztyp: Movable
Fensteröffnung | H2 Ebene +1 | 1155Fen0813749796 | m³ | 0 | Fensterarbeiten | Fensteröffnung | 0 | 3.75 |  | 1155Wa 0000197420 | 0 | - | 0,51 | AllplanAttributes - U-Wert: 0.9; Schallschutzklasse: 32; Sonnenschutztyp: Movable
Fensteröffnung | H2 Ebene +1 | 1155Fen0813749792 | m³ | 0 | Fensterarbeiten | Fensteröffnung | 0 | 3.75 |  | 1155Wa 0000197420 | 0 | - | 0,51 | AllplanAttributes - U-Wert: 0.9; Schallschutzklasse: 32; Sonnenschutztyp: Movable
Fensteröffnung | H2 Ebene +1 | 1155Fen0813749783 | m³ | 0 | Fensterarbeiten | Fensteröffnung | 0 | 3.75 |  | 1155Wa 0000197420 | 0 | - | 0,51 | AllplanAttributes - U-Wert: 0.9; Schallschutzklasse: 32; Sonnenschutztyp: Movable
Fensteröffnung | H2 Ebene +1 | 1155Fen0813749776 | m³ | 0 | Fensterarbeiten | Fensteröffnung | 0 | 3.75 |  | 1155Wa 0000197420 | 0 | - | 0,51 | AllplanAttributes - U-Wert: 0.9; Schallschutzklasse: 32; Sonnenschutztyp: Movable
Fensteröffnung | H2 Ebene +1 | 1155Fen0813749795 | m³ | 0 | Fensterarbeiten | Fensteröffnung | 0 | 3.75 |  | 1155Wa 0000197419 | 0 | - | 0,51 | AllplanAttributes - U-Wert: 0.9; Schallschutzklasse: 32; Sonnenschutztyp: Movable
Fensteröffnung | H2 Ebene +1 | 1155Fen0813749791 | m³ | 0 | Fensterarbeiten | Fensteröffnung | 0 | 3.75 |  | 1155Wa 0000197419 | 0 | - | 0,51 | AllplanAttributes - U-Wert: 0.9; Schallschutzklasse: 32; Sonnenschutztyp: Movable
Fensteröffnung | H2 Ebene +1 | 1155Fen0813749781 | m³ | 0 | Fensterarbeiten | Fensteröffnung | 0 | 3.75 |  | 1155Wa 0000197419 | 0 | - | 0,51 | AllplanAttributes - U-Wert: 0.9; Schallschutzklasse: 32; Sonnenschutztyp: Movable
Fensteröffnung | H2 Ebene +1 | 1155Fen0813749779 | m³ | 0 | Fensterarbeiten | Fensteröffnung | 0 | 3.75 |  | 1155Wa 0000197419 | 0 | - | 0,51 | AllplanAttributes - U-Wert: 0.9; Schallschutzklasse: 32; Sonnenschutztyp: Movable
Fensteröffnung | H2 Ebene +1 | 1155Fen0813749798 | m² | 0 | Fensterarbeiten | Fensteröffnung | 0 | 3.75 |  | 1155Wa 0000197418 | 0 | - | 0,51 | AllplanAttributes - U-Wert: 0.9; Schallschutzklasse: 32; Sonnenschutztyp: Movable
Fensteröffnung | H2 Ebene +1 | 1155Fen0813749782 | m² | 0 | Fensterarbeiten | Fensteröffnung | 0 | 3.75 |  | 1155Wa 0000197418 | 0 | - | 0,51 | AllplanAttributes - U-Wert: 0.9; Schallschutzklasse: 32; Sonnenschutztyp: Movable
Fensteröffnung | H2 Ebene +1 | 1155Fen0813749780 | m² | 0 | Fensterarbeiten | Fensteröffnung | 0 | 3.75 |  | 1155Wa 0000197418 | 0 | - | 0,51 | AllplanAttributes - U-Wert: 0.9; Schallschutzklasse: 32; Sonnenschutztyp: Movable
Fensteröffnung | H2 Ebene +1 | 1155Fen0813749778 | m² | 0 | Fensterarbeiten | Fensteröffnung | 0 | 3.75 |  | 1155Wa 0000197418 | 0 | - | 0,51 | AllplanAttributes - U-Wert: 0.9; Schallschutzklasse: 32; Sonnenschutztyp: Movable
Fensteröffnung | H2 Ebene +1 | 1155Fen0813749790 | m² | 0 | Fensterarbeiten | Fensteröffnung | 0 | 3.75 | NEW | 1155Wa 0000197417 | 0 | - | 0,51 | AllplanAttributes - U-Wert: 0.9; Schallschutzklasse: 32; Sonnenschutztyp: Movable
Fensteröffnung | H2 Ebene +1 | 1155Fen0813749787 | m² | 0 | Fensterarbeiten | Fensteröffnung | 0 | 3.75 | NEW | 1155Wa 0000197417 | 0 | - | 0,51 | AllplanAttributes - U-Wert: 0.9; Schallschutzklasse: 32; Sonnenschutztyp: Movable
Fensteröffnung | H2 Ebene +1 | 1155Fen0813749785 | m² | 0 | Fensterarbeiten | Fensteröffnung | 0 | 3.75 | NEW | 1155Wa 0000197417 | 0 | - | 0,51 | AllplanAttributes - U-Wert: 0.9; Schallschutzklasse: 32; Sonnenschutztyp: Movable
Fensteröffnung | H2 Ebene +1 | 1155Fen0813749777 | m² | 0 | Fensterarbeiten | Fensteröffnung | 0 | 3.75 | NEW | 1155Wa 0000197417 | 0 | - | 0,51 | AllplanAttributes - U-Wert: 0.9; Schallschutzklasse: 32; Sonnenschutztyp: Movable
Fensteröffnung | H2 Ebene +1 | 1155Fen0813749799 | m² | 0 | Fensterarbeiten | Fensteröffnung | 0 | 3.75 | NEW | 1155Wa 0000197416 | 0 | - | 0,51 | AllplanAttributes - U-Wert: 0.9; Schallschutzklasse: 32; Sonnenschutztyp: Movable
Fensteröffnung | H2 Ebene +1 | 1155Fen0813749797 | m² | 0 | Fensterarbeiten | Fensteröffnung | 0 | 3.75 | NEW | 1155Wa 0000197416 | 0 | - | 0,51 | AllplanAttributes - U-Wert: 0.9; Schallschutzklasse: 32; Sonnenschutztyp: Movable
Fensteröffnung | H2 Ebene +1 | 1155Fen0813749786 | m² | 0 | Fensterarbeiten | Fensteröffnung | 0 | 3.75 | NEW | 1155Wa 0000197416 | 0 | - | 0,51 | AllplanAttributes - U-Wert: 0.9; Schallschutzklasse: 32; Sonnenschutztyp: Movable
Fensteröffnung | H2 Ebene +1 | 1155Fen0813749784 | m² | 0 | Fensterarbeiten | Fensteröffnung | 0 | 3.75 | NEW | 1155Wa 0000197416 | 0 | - | 0,51 | AllplanAttributes - U-Wert: 0.9; Schallschutzklasse: 32; Sonnenschutztyp: Movable
Fensteröffnung | H2 Ebene +1 | 1155Fen0813749794 | m² | 0 | Fensterarbeiten | Fensteröffnung | 0 | 3.75 | NEW | 1155Wa 0000197415 | 0 | - | 0,51 | AllplanAttributes - U-Wert: 0.9; Schallschutzklasse: 32; Sonnenschutztyp: Movable
Fensteröffnung | H2 Ebene +1 | 1155Fen0813749793 | m² | 0 | Fensterarbeiten | Fensteröffnung | 0 | 3.75 | NEW | 1155Wa 0000197415 | 0 | - | 0,51 | AllplanAttributes - U-Wert: 0.9; Schallschutzklasse: 32; Sonnenschutztyp: Movable
Fensteröffnung | H2 Ebene +1 | 1155Fen0813749789 | m² | 0 | Fensterarbeiten | Fensteröffnung | 0 | 3.75 | NEW | 1155Wa 0000197415 | 0 | - | 0,51 | AllplanAttributes - U-Wert: 0.9; Schallschutzklasse: 32; Sonnenschutztyp: Movable
Fensteröffnung | H2 Ebene +1 | 1155Fen0813749788 | m² | 0 | Fensterarbeiten | Fensteröffnung | 0 | 3.75 | NEW | 1155Wa 0000197415 | 0 | - | 0,51 | AllplanAttributes - U-Wert: 0.9; Schallschutzklasse: 32; Sonnenschutztyp: Movable
Fensteröffnung | H2 Ebene +1 | 1155Fen0000011852 | m² |  | Wärmedämm-Verbundsysteme | Fensteröffnung |  | 3.75 | NEW | 1155Wa 0000001868 | 0 | - | 0,51 | AllplanAttributes - Material: Fensterelement; Tragendes Bauteil: no; Brandabschnittsdefinierendes Bauteil: no; U-Wert: 0.9; Schallschutzklasse: 32; Sonnenschutztyp: Movable
Fensteröffnung | H2 Ebene +1 | 1155Fen0000011855 | m³ | 0 | Wärmedämm-Verbundsysteme | Fensteröffnung | 0 | 3.75 | NEW | 1155Wa 0000001872 | 0 | - | 0,51 | AllplanAttributes - Material: Fensterelement; Außenliegend: yes; U-Wert: 0.9; Schallschutzklasse: 32; Sonnenschutztyp: Movable
Fensteröffnung | H2 Ebene +1 | 1155Fen0000011857 | m³ | 0 | Wärmedämm-Verbundsysteme | Fensteröffnung | 0 | 3.75 | NEW | 1155Wa 0000001876 | 0 | - | 0,51 | AllplanAttributes - U-Wert: 0.9; Schallschutzklasse: 32; Sonnenschutztyp: Movable
Fensteröffnung | H2 Ebene +1 | 1155Fen0000011859 | m² | 0 | Wärmedämm-Verbundsysteme | Fensteröffnung | 0 | 3.75 | NEW | 1155Wa 0000001880 | 0 | - | 0,51 | AllplanAttributes - U-Wert: 0.9; Schallschutzklasse: 32; Sonnenschutztyp: Movable
Fensteröffnung | H2 Ebene +1 | 1155Fen0000011861 | m² | 0 | Wärmedämm-Verbundsysteme | Fensteröffnung | 0 | 3.75 | NEW | 1155Wa 0000001884 | 0 | - | 0,51 | AllplanAttributes - U-Wert: 0.9; Schallschutzklasse: 32; Sonnenschutztyp: Movable
Fensteröffnung | H2 Ebene +1 | 1155Fen0000011863 | m² | 0 | Wärmedämm-Verbundsysteme | Fensteröffnung | 0 | 3.75 | NEW | 1155Wa 0000001888 | 0 | - | 0,51 | AllplanAttributes - U-Wert: 0.9; Schallschutzklasse: 32; Sonnenschutztyp: Movable
Fensteröffnung | H2 Ebene +1 | 1155Fen0000011865 | m² | 0 | Wärmedämm-Verbundsysteme | Fensteröffnung | 0 | 3.75 | NEW | 1155Wa 0000001892 | 0 | - | 0,51 | AllplanAttributes - U-Wert: 0.9; Schallschutzklasse: 32; Sonnenschutztyp: Movable
Fensteröffnung | H2 Ebene +1 | 1155Fen0000005480 | m² |  | Fensterarbeiten | Fensteröffnung |  | 3.75 |  | 1155Wa 0000002699 | 0 | - | 0,51 | AllplanAttributes - U-Wert: 0.9; Schallschutzklasse: 32; Sonnenschutztyp: Movable
Fensteröffnung | H2 Ebene +1 | 1155Fen0000005472 | m² |  | Fensterarbeiten | Fensteröffnung |  | 3.75 |  | 1155Wa 0000002699 | 0 | - | 0,51 | AllplanAttributes - U-Wert: 0.9; Schallschutzklasse: 32; Sonnenschutztyp: Movable
Fensteröffnung | H2 Ebene +1 | 1155Fen0000005468 | m² |  | Fensterarbeiten | Fensteröffnung |  | 3.75 |  | 1155Wa 0000002699 | 0 | - | 0,51 | AllplanAttributes - U-Wert: 0.9; Schallschutzklasse: 32; Sonnenschutztyp: Movable
Fensteröffnung | H2 Ebene +1 | 1155Fen0000005476 | m² |  | Fensterarbeiten | Fensteröffnung |  | 3.75 |  | 1155Wa 0000002699 | 0 | - | 0,51 | AllplanAttributes - U-Wert: 0.9; Schallschutzklasse: 32; Sonnenschutztyp: Movable
Fensteröffnung | H2 Ebene +1 | 1155Fen0000002454 | m³ | 0 | Fensterarbeiten | Fensteröffnung | 0 | 3.75 |  | 1155Wa 0000002706 | 0 | - | 0,51 | AllplanAttributes - U-Wert: 0.9; Schallschutzklasse: 32; Sonnenschutztyp: Movable
Fensteröffnung | H2 Ebene +1 | 1155Fen0000002466 | m³ | 0 | Fensterarbeiten | Fensteröffnung | 0 | 3.75 |  | 1155Wa 0000002706 | 0 | - | 0,51 | AllplanAttributes - U-Wert: 0.9; Schallschutzklasse: 32; Sonnenschutztyp: Movable
Fensteröffnung | H2 Ebene +1 | 1155Fen0000002430 | m³ | 0 | Fensterarbeiten | Fensteröffnung | 0 | 3.75 |  | 1155Wa 0000002706 | 0 | - | 0,51 | AllplanAttributes - U-Wert: 0.9; Schallschutzklasse: 32; Sonnenschutztyp: Movable
Fensteröffnung | H2 Ebene +1 | 1155Fen0000002442 | m³ | 0 | Fensterarbeiten | Fensteröffnung | 0 | 3.75 |  | 1155Wa 0000002706 | 0 | - | 0,51 | AllplanAttributes - U-Wert: 0.9; Schallschutzklasse: 32; Sonnenschutztyp: Movable
Fensteröffnung | H2 Ebene +1 | 1155Fen0000002468 | m³ | 0 | Fensterarbeiten | Fensteröffnung | 0 | 3.75 |  | 1155Wa 0000002713 | 0 | - | 0,51 | AllplanAttributes - U-Wert: 0.9; Schallschutzklasse: 32; Sonnenschutztyp: Movable
Fensteröffnung | H2 Ebene +1 | 1155Fen0000002432 | m³ | 0 | Fensterarbeiten | Fensteröffnung | 0 | 3.75 |  | 1155Wa 0000002713 | 0 | - | 0,51 | AllplanAttributes - U-Wert: 0.9; Schallschutzklasse: 32; Sonnenschutztyp: Movable
Fensteröffnung | H2 Ebene +1 | 1155Fen0000002456 | m³ | 0 | Fensterarbeiten | Fensteröffnung | 0 | 3.75 |  | 1155Wa 0000002713 | 0 | - | 0,51 | AllplanAttributes - U-Wert: 0.9; Schallschutzklasse: 32; Sonnenschutztyp: Movable
Fensteröffnung | H2 Ebene +1 | 1155Fen0000002444 | m³ | 0 | Fensterarbeiten | Fensteröffnung | 0 | 3.75 |  | 1155Wa 0000002713 | 0 | - | 0,51 | AllplanAttributes - U-Wert: 0.9; Schallschutzklasse: 32; Sonnenschutztyp: Movable
Fensteröffnung | H2 Ebene +1 | 1155Fen0000002470 | m² | 0 | Fensterarbeiten | Fensteröffnung | 0 | 3.75 |  | 1155Wa 0000002720 | 0 | - | 0,51 | AllplanAttributes - U-Wert: 0.9; Schallschutzklasse: 32; Sonnenschutztyp: Movable
Fensteröffnung | H2 Ebene +1 | 1155Fen0000002446 | m² | 0 | Fensterarbeiten | Fensteröffnung | 0 | 3.75 |  | 1155Wa 0000002720 | 0 | - | 0,51 | AllplanAttributes - U-Wert: 0.9; Schallschutzklasse: 32; Sonnenschutztyp: Movable
Fensteröffnung | H2 Ebene +1 | 1155Fen0000002458 | m² | 0 | Fensterarbeiten | Fensteröffnung | 0 | 3.75 |  | 1155Wa 0000002720 | 0 | - | 0,51 | AllplanAttributes - U-Wert: 0.9; Schallschutzklasse: 32; Sonnenschutztyp: Movable
Fensteröffnung | H2 Ebene +1 | 1155Fen0000002434 | m² | 0 | Fensterarbeiten | Fensteröffnung | 0 | 3.75 |  | 1155Wa 0000002720 | 0 | - | 0,51 | AllplanAttributes - U-Wert: 0.9; Schallschutzklasse: 32; Sonnenschutztyp: Movable
Fensteröffnung | H2 Ebene +1 | 1155Fen0000002448 | m² | 0 | Fensterarbeiten | Fensteröffnung | 0 | 3.75 | NEW | 1155Wa 0000002727 | 0 | - | 0,51 | AllplanAttributes - U-Wert: 0.9; Schallschutzklasse: 32; Sonnenschutztyp: Movable
Fensteröffnung | H2 Ebene +1 | 1155Fen0000002472 | m² | 0 | Fensterarbeiten | Fensteröffnung | 0 | 3.75 | NEW | 1155Wa 0000002727 | 0 | - | 0,51 | AllplanAttributes - U-Wert: 0.9; Schallschutzklasse: 32; Sonnenschutztyp: Movable
Fensteröffnung | H2 Ebene +1 | 1155Fen0000002436 | m² | 0 | Fensterarbeiten | Fensteröffnung | 0 | 3.75 | NEW | 1155Wa 0000002727 | 0 | - | 0,51 | AllplanAttributes - U-Wert: 0.9; Schallschutzklasse: 32; Sonnenschutztyp: Movable
Fensteröffnung | H2 Ebene +1 | 1155Fen0000002460 | m² | 0 | Fensterarbeiten | Fensteröffnung | 0 | 3.75 | NEW | 1155Wa 0000002727 | 0 | - | 0,51 | AllplanAttributes - U-Wert: 0.9; Schallschutzklasse: 32; Sonnenschutztyp: Movable
Fensteröffnung | H2 Ebene +1 | 1155Fen0000002474 | m² | 0 | Fensterarbeiten | Fensteröffnung | 0 | 3.75 | NEW | 1155Wa 0000002734 | 0 | - | 0,51 | AllplanAttributes - U-Wert: 0.9; Schallschutzklasse: 32; Sonnenschutztyp: Movable
Fensteröffnung | H2 Ebene +1 | 1155Fen0000002438 | m² | 0 | Fensterarbeiten | Fensteröffnung | 0 | 3.75 | NEW | 1155Wa 0000002734 | 0 | - | 0,51 | AllplanAttributes - U-Wert: 0.9; Schallschutzklasse: 32; Sonnenschutztyp: Movable
Fensteröffnung | H2 Ebene +1 | 1155Fen0000002450 | m² | 0 | Fensterarbeiten | Fensteröffnung | 0 | 3.75 | NEW | 1155Wa 0000002734 | 0 | - | 0,51 | AllplanAttributes - U-Wert: 0.9; Schallschutzklasse: 32; Sonnenschutztyp: Movable
Fensteröffnung | H2 Ebene +1 | 1155Fen0000002462 | m² | 0 | Fensterarbeiten | Fensteröffnung | 0 | 3.75 | NEW | 1155Wa 0000002734 | 0 | - | 0,51 | AllplanAttributes - U-Wert: 0.9; Schallschutzklasse: 32; Sonnenschutztyp: Movable
Fensteröffnung | H2 Ebene +1 | 1155Fen0000002476 | m² | 0 | Fensterarbeiten | Fensteröffnung | 0 | 3.75 | NEW | 1155Wa 0000002741 | 0 | - | 0,51 | AllplanAttributes - U-Wert: 0.9; Schallschutzklasse: 32; Sonnenschutztyp: Movable
Fensteröffnung | H2 Ebene +1 | 1155Fen0000002452 | m² | 0 | Fensterarbeiten | Fensteröffnung | 0 | 3.75 | NEW | 1155Wa 0000002741 | 0 | - | 0,51 | AllplanAttributes - U-Wert: 0.9; Schallschutzklasse: 32; Sonnenschutztyp: Movable
Fensteröffnung | H2 Ebene +1 | 1155Fen0000002440 | m² | 0 | Fensterarbeiten | Fensteröffnung | 0 | 3.75 | NEW | 1155Wa 0000002741 | 0 | - | 0,51 | AllplanAttributes - U-Wert: 0.9; Schallschutzklasse: 32; Sonnenschutztyp: Movable
Fensteröffnung | H2 Ebene +1 | 1155Fen0000002464 | m² | 0 | Fensterarbeiten | Fensteröffnung | 0 | 3.75 | NEW | 1155Wa 0000002741 | 0 | - | 0,51 | AllplanAttributes - U-Wert: 0.9; Schallschutzklasse: 32; Sonnenschutztyp: Movable
Fensteröffnung | H2 Ebene +1 | 1155Fen0000191469 | m² |  | Wärmedämm-Verbundsysteme | Fensteröffnung |  | 3.75 | NEW | 1155Wa 0000191477 | 0 | - | 0,51 | AllplanAttributes - Material: Fensterelement; Tragendes Bauteil: no; Brandabschnittsdefinierendes Bauteil: no; U-Wert: 0.9; Schallschutzklasse: 32; Sonnenschutztyp: Movable
Fensteröffnung | H2 Ebene +1 | 1155Fen0000191467 | m² |  | Wärmedämm-Verbundsysteme | Fensteröffnung |  | 3.75 | NEW | 1155Wa 0000191477 | 0 | - | 0,51 | AllplanAttributes - Material: Fensterelement; Tragendes Bauteil: no; Brandabschnittsdefinierendes Bauteil: no; U-Wert: 0.9; Schallschutzklasse: 32; Sonnenschutztyp: Movable
Fensteröffnung | H2 Ebene +1 | 1155Fen0000191463 | m³ | 0 | Wärmedämm-Verbundsysteme | Fensteröffnung | 0 | 3.75 | NEW | 1155Wa 0000191478 | 0 | - | 0,51 | AllplanAttributes - Material: Fensterelement; Außenliegend: yes; U-Wert: 0.9; Schallschutzklasse: 32; Sonnenschutztyp: Movable
Fensteröffnung | H2 Ebene +1 | 1155Fen0000191461 | m³ | 0 | Wärmedämm-Verbundsysteme | Fensteröffnung | 0 | 3.75 | NEW | 1155Wa 0000191478 | 0 | - | 0,51 | AllplanAttributes - Material: Fensterelement; Außenliegend: yes; U-Wert: 0.9; Schallschutzklasse: 32; Sonnenschutztyp: Movable
Fensteröffnung | H2 Ebene +1 | 1155Fen0000191464 | m³ | 0 | Wärmedämm-Verbundsysteme | Fensteröffnung | 0 | 3.75 | NEW | 1155Wa 0000191479 | 0 | - | 0,51 | AllplanAttributes - U-Wert: 0.9; Schallschutzklasse: 32; Sonnenschutztyp: Movable
Fensteröffnung | H2 Ebene +1 | 1155Fen0000191462 | m³ | 0 | Wärmedämm-Verbundsysteme | Fensteröffnung | 0 | 3.75 | NEW | 1155Wa 0000191479 | 0 | - | 0,51 | AllplanAttributes - U-Wert: 0.9; Schallschutzklasse: 32; Sonnenschutztyp: Movable
Fensteröffnung | H2 Ebene +1 | 1155Fen0000191466 | m² | 0 | Wärmedämm-Verbundsysteme | Fensteröffnung | 0 | 3.75 | NEW | 1155Wa 0000191480 | 0 | - | 0,51 | AllplanAttributes - U-Wert: 0.9; Schallschutzklasse: 32; Sonnenschutztyp: Movable
Fensteröffnung | H2 Ebene +1 | 1155Fen0000191465 | m² | 0 | Wärmedämm-Verbundsysteme | Fensteröffnung | 0 | 3.75 | NEW | 1155Wa 0000191480 | 0 | - | 0,51 | AllplanAttributes - U-Wert: 0.9; Schallschutzklasse: 32; Sonnenschutztyp: Movable
Fensteröffnung | H2 Ebene +1 | 1155Fen0000191458 | m² | 0 | Wärmedämm-Verbundsysteme | Fensteröffnung | 0 | 3.75 | NEW | 1155Wa 0000191481 | 0 | - | 0,51 | AllplanAttributes - U-Wert: 0.9; Schallschutzklasse: 32; Sonnenschutztyp: Movable
Fensteröffnung | H2 Ebene +1 | 1155Fen0000191455 | m² | 0 | Wärmedämm-Verbundsysteme | Fensteröffnung | 0 | 3.75 | NEW | 1155Wa 0000191481 | 0 | - | 0,51 | AllplanAttributes - U-Wert: 0.9; Schallschutzklasse: 32; Sonnenschutztyp: Movable
Fensteröffnung | H2 Ebene +1 | 1155Fen0000191456 | m² | 0 | Wärmedämm-Verbundsysteme | Fensteröffnung | 0 | 3.75 | NEW | 1155Wa 0000191482 | 0 | - | 0,51 | AllplanAttributes - U-Wert: 0.9; Schallschutzklasse: 32; Sonnenschutztyp: Movable
Fensteröffnung | H2 Ebene +1 | 1155Fen0000191459 | m² | 0 | Wärmedämm-Verbundsysteme | Fensteröffnung | 0 | 3.75 | NEW | 1155Wa 0000191482 | 0 | - | 0,51 | AllplanAttributes - U-Wert: 0.9; Schallschutzklasse: 32; Sonnenschutztyp: Movable
Fensteröffnung | H2 Ebene +1 | 1155Fen0000191457 | m² | 0 | Wärmedämm-Verbundsysteme | Fensteröffnung | 0 | 3.75 | NEW | 1155Wa 0000191483 | 0 | - | 0,51 | AllplanAttributes - U-Wert: 0.9; Schallschutzklasse: 32; Sonnenschutztyp: Movable
Fensteröffnung | H2 Ebene +1 | 1155Fen0000191460 | m² | 0 | Wärmedämm-Verbundsysteme | Fensteröffnung | 0 | 3.75 | NEW | 1155Wa 0000191483 | 0 | - | 0,51 | AllplanAttributes - U-Wert: 0.9; Schallschutzklasse: 32; Sonnenschutztyp: Movable
Fensteröffnung | H2 Ebene +1 | 1155Fen0000011963 | m² |  | Wärmedämm-Verbundsysteme | Fensteröffnung |  | 3.75 | NEW | 1155Wa 0000001093 | 0 | - | 0,51 | AllplanAttributes - Material: Fensterelement; Tragendes Bauteil: no; Brandabschnittsdefinierendes Bauteil: no; U-Wert: 0.9; Schallschutzklasse: 32; Sonnenschutztyp: Movable
Fensteröffnung | H2 Ebene +1 | 1155Fen0000011960 | m² |  | Wärmedämm-Verbundsysteme | Fensteröffnung |  | 3.75 | NEW | 1155Wa 0000001093 | 0 | - | 0,51 | AllplanAttributes - Material: Fensterelement; Tragendes Bauteil: no; Brandabschnittsdefinierendes Bauteil: no; U-Wert: 0.9; Schallschutzklasse: 32; Sonnenschutztyp: Movable
Fensteröffnung | H2 Ebene +1 | 1155Fen0000011981 | m³ | 0 | Wärmedämm-Verbundsysteme | Fensteröffnung | 0 | 3.75 | NEW | 1155Wa 0000001097 | 0 | - | 0,51 | AllplanAttributes - Material: Fensterelement; Außenliegend: yes; U-Wert: 0.9; Schallschutzklasse: 32; Sonnenschutztyp: Movable
Fensteröffnung | H2 Ebene +1 | 1155Fen0000011993 | m³ | 0 | Wärmedämm-Verbundsysteme | Fensteröffnung | 0 | 3.75 | NEW | 1155Wa 0000001097 | 0 | - | 0,51 | AllplanAttributes - Material: Fensterelement; Außenliegend: yes; U-Wert: 0.9; Schallschutzklasse: 32; Sonnenschutztyp: Movable
Fensteröffnung | H2 Ebene +1 | 1155Fen0000011983 | m³ | 0 | Wärmedämm-Verbundsysteme | Fensteröffnung | 0 | 3.75 | NEW | 1155Wa 0000001117 | 0 | - | 0,51 | AllplanAttributes - U-Wert: 0.9; Schallschutzklasse: 32; Sonnenschutztyp: Movable
Fensteröffnung | H2 Ebene +1 | 1155Fen0000011995 | m³ | 0 | Wärmedämm-Verbundsysteme | Fensteröffnung | 0 | 3.75 | NEW | 1155Wa 0000001117 | 0 | - | 0,51 | AllplanAttributes - U-Wert: 0.9; Schallschutzklasse: 32; Sonnenschutztyp: Movable
Fensteröffnung | H2 Ebene +1 | 1155Fen0000011985 | m² | 0 | Wärmedämm-Verbundsysteme | Fensteröffnung | 0 | 3.75 | NEW | 1155Wa 0000001113 | 0 | - | 0,51 | AllplanAttributes - U-Wert: 0.9; Schallschutzklasse: 32; Sonnenschutztyp: Movable
Fensteröffnung | H2 Ebene +1 | 1155Fen0000011997 | m² | 0 | Wärmedämm-Verbundsysteme | Fensteröffnung | 0 | 3.75 | NEW | 1155Wa 0000001113 | 0 | - | 0,51 | AllplanAttributes - U-Wert: 0.9; Schallschutzklasse: 32; Sonnenschutztyp: Movable
Fensteröffnung | H2 Ebene +1 | 1155Fen0000011987 | m² | 0 | Wärmedämm-Verbundsysteme | Fensteröffnung | 0 | 3.75 | NEW | 1155Wa 0000001109 | 0 | - | 0,51 | AllplanAttributes - U-Wert: 0.9; Schallschutzklasse: 32; Sonnenschutztyp: Movable
Fensteröffnung | H2 Ebene +1 | 1155Fen0000011999 | m² | 0 | Wärmedämm-Verbundsysteme | Fensteröffnung | 0 | 3.75 | NEW | 1155Wa 0000001109 | 0 | - | 0,51 | AllplanAttributes - U-Wert: 0.9; Schallschutzklasse: 32; Sonnenschutztyp: Movable
Fensteröffnung | H2 Ebene +1 | 1155Fen0000012001 | m² | 0 | Wärmedämm-Verbundsysteme | Fensteröffnung | 0 | 3.75 | NEW | 1155Wa 0000001105 | 0 | - | 0,51 | AllplanAttributes - U-Wert: 0.9; Schallschutzklasse: 32; Sonnenschutztyp: Movable
Fensteröffnung | H2 Ebene +1 | 1155Fen0000011989 | m² | 0 | Wärmedämm-Verbundsysteme | Fensteröffnung | 0 | 3.75 | NEW | 1155Wa 0000001105 | 0 | - | 0,51 | AllplanAttributes - U-Wert: 0.9; Schallschutzklasse: 32; Sonnenschutztyp: Movable
Fensteröffnung | H2 Ebene +1 | 1155Fen0000011991 | m² | 0 | Wärmedämm-Verbundsysteme | Fensteröffnung | 0 | 3.75 | NEW | 1155Wa 0000001101 | 0 | - | 0,51 | AllplanAttributes - U-Wert: 0.9; Schallschutzklasse: 32; Sonnenschutztyp: Movable
Fensteröffnung | H2 Ebene +1 | 1155Fen0000012003 | m² | 0 | Wärmedämm-Verbundsysteme | Fensteröffnung | 0 | 3.75 | NEW | 1155Wa 0000001101 | 0 | - | 0,51 | AllplanAttributes - U-Wert: 0.9; Schallschutzklasse: 32; Sonnenschutztyp: Movable
Fensteröffnung | H2 Ebene +1 | 1155Fen2005679097 | m² |  | Metallbau-, Schlosserarbeiten | Fensteröffnung |  |  | NEW
Fensteröffnung | H2 Ebene +1 | 1155Fen2005679098 | m² | 0 | Metallbau-, Schlosserarbeiten | Fensteröffnung | 0 |  | NEW
Fensteröffnung | H2 Ebene +1 | 1155Fen2005680074 | m² |  | Metallbau-, Schlosserarbeiten | Fensteröffnung |  |  | NEW
Fensteröffnung | H2 Ebene +1 | 1155Fen2005680075 | m² | 0 | Metallbau-, Schlosserarbeiten | Fensteröffnung | 0 |  | NEW
Fensteröffnung | H2 Ebene +1 | 1155Fen0000124216 | m² |  | Fensterarbeiten | Fensteröffnung |  | 3.75 |  | 1155Wa 0000121234 | 0 | - | 0,51 | AllplanAttributes - U-Wert: 0.9; Schallschutzklasse: 32; Sonnenschutztyp: Movable
Fensteröffnung | H2 Ebene +1 | 1155Fen0000123624 | m² |  | Betonarbeiten | Fensteröffnung |  | 3.75 | NEW | 1155Wa 0000121234 | 0 | - | 0,51 | AllplanAttributes - U-Wert: 0.9; Schallschutzklasse: 32; Sonnenschutztyp: Movable
Fensteröffnung | H2 Ebene +1 | 1155Fen0000124215 | m³ | 0 | Fensterarbeiten | Fensteröffnung | 0 | 3.75 |  | 1155Wa 0000121235 | 0 | - | 0,51 | AllplanAttributes - U-Wert: 0.9; Schallschutzklasse: 32; Sonnenschutztyp: Movable
Fensteröffnung | H2 Ebene +1 | 1155Fen0000123625 | m³ | 0 | Betonarbeiten | Fensteröffnung | 0 | 3.75 | NEW | 1155Wa 0000121235 | 0 | - | 0,51 | AllplanAttributes - Material: Fensterelement; U-Wert: 0.9; Schallschutzklasse: 32; Sonnenschutztyp: Movable
Fensteröffnung | H2 Ebene +1 | 1155Fen0000124214 | m³ | 0 | Fensterarbeiten | Fensteröffnung | 0 | 3.75 |  | 1155Wa 0000121240 | 0 | - | 0,51 | AllplanAttributes - U-Wert: 0.9; Schallschutzklasse: 32; Sonnenschutztyp: Movable
Fensteröffnung | H2 Ebene +1 | 1155Fen0000123626 | m³ | 0 | Betonarbeiten | Fensteröffnung | 0 | 3.75 | NEW | 1155Wa 0000121240 | 0 | - | 0,51 | AllplanAttributes - U-Wert: 0.9; Schallschutzklasse: 32; Sonnenschutztyp: Movable
Fensteröffnung | H2 Ebene +1 | 1155Fen0000124213 | m² | 0 | Fensterarbeiten | Fensteröffnung | 0 | 3.75 |  | 1155Wa 0000121239 | 0 | - | 0,51 | AllplanAttributes - U-Wert: 0.9; Schallschutzklasse: 32; Sonnenschutztyp: Movable
Fensteröffnung | H2 Ebene +1 | 1155Fen0000123627 | m² | 0 | Betonarbeiten | Fensteröffnung | 0 | 3.75 | NEW | 1155Wa 0000121239 | 0 | - | 0,51 | AllplanAttributes - U-Wert: 0.9; Schallschutzklasse: 32; Sonnenschutztyp: Movable
Fensteröffnung | H2 Ebene +1 | 1155Fen0000124212 | m² | 0 | Fensterarbeiten | Fensteröffnung | 0 | 3.75 | NEW | 1155Wa 0000121238 | 0 | - | 0,51 | AllplanAttributes - U-Wert: 0.9; Schallschutzklasse: 32; Sonnenschutztyp: Movable
Fensteröffnung | H2 Ebene +1 | 1155Fen0000123628 | m² | 0 | Betonarbeiten | Fensteröffnung | 0 | 3.75 | NEW | 1155Wa 0000121238 | 0 | - | 0,51 | AllplanAttributes - U-Wert: 0.9; Schallschutzklasse: 32; Sonnenschutztyp: Movable
Fensteröffnung | H2 Ebene +1 | 1155Fen0000124211 | m² | 0 | Fensterarbeiten | Fensteröffnung | 0 | 3.75 | NEW | 1155Wa 0000121237 | 0 | - | 0,51 | AllplanAttributes - U-Wert: 0.9; Schallschutzklasse: 32; Sonnenschutztyp: Movable
Fensteröffnung | H2 Ebene +1 | 1155Fen0000123629 | m² | 0 | Betonarbeiten | Fensteröffnung | 0 | 3.75 | NEW | 1155Wa 0000121237 | 0 | - | 0,51 | AllplanAttributes - U-Wert: 0.9; Schallschutzklasse: 32; Sonnenschutztyp: Movable
Fensteröffnung | H2 Ebene +1 | 1155Fen0000124210 | m² | 0 | Fensterarbeiten | Fensteröffnung | 0 | 3.75 | NEW | 1155Wa 0000121236 | 0 | - | 0,51 | AllplanAttributes - U-Wert: 0.9; Schallschutzklasse: 32; Sonnenschutztyp: Movable
Fensteröffnung | H2 Ebene +1 | 1155Fen0000123630 | m² | 0 | Betonarbeiten | Fensteröffnung | 0 | 3.75 | NEW | 1155Wa 0000121236 | 0 | - | 0,51 | AllplanAttributes - ash D_Detailverweis: FSE1; ash D_Plannummer: D786; U-Wert: 0.9; Schallschutzklasse: 32; Sonnenschutztyp: Movable
Fensteröffnung | H2 Ebene +1 | 1155Fen2005702244 | m² |  | Fensterarbeiten | Fensteröffnung |  | 3.75 |  | 1155Wa 0000001796 | 0 | - | 0,51 | AllplanAttributes - U-Wert: 0.9; Schallschutzklasse: 32; Sonnenschutztyp: Movable
Fensteröffnung | H2 Ebene +1 | 1155Fen2005702241 | m³ | 0 | Fensterarbeiten | Fensteröffnung | 0 | 3.75 |  | 1155Wa 0000001793 | 0 | - | 0,51 | AllplanAttributes - U-Wert: 0.9; Schallschutzklasse: 32; Sonnenschutztyp: Movable
Fensteröffnung | H2 Ebene +1 | 1155Fen2005702243 | m³ | 0 | Fensterarbeiten | Fensteröffnung | 0 | 3.75 |  | 1155Wa 0000001790 | 0 | - | 0,51 | AllplanAttributes - U-Wert: 0.9; Schallschutzklasse: 32; Sonnenschutztyp: Movable
Fensteröffnung | H2 Ebene +1 | 1155Fen2005702245 | m² | 0 | Fensterarbeiten | Fensteröffnung | 0 | 3.75 |  | 1155Wa 0000001786 | 0 | - | 0,51 | AllplanAttributes - U-Wert: 0.9; Schallschutzklasse: 32; Sonnenschutztyp: Movable
Fensteröffnung | H2 Ebene +1 | 1155Fen2005704460 | m² |  | Fensterarbeiten | Fensteröffnung |  | 3.75 |  | 1155Wa 0000198239 | 0 | - | 0,51 | AllplanAttributes - U-Wert: 0.9; Schallschutzklasse: 32; Sonnenschutztyp: Movable
Fensteröffnung | H2 Ebene +1 | 1155Fen2005704464 | m³ | 0 | Fensterarbeiten | Fensteröffnung | 0 | 3.75 |  | 1155Wa 0000198238 | 0 | - | 0,51 | AllplanAttributes - U-Wert: 0.9; Schallschutzklasse: 32; Sonnenschutztyp: Movable
Fensteröffnung | H2 Ebene +1 | 1155Fen2005704463 | m³ | 0 | Fensterarbeiten | Fensteröffnung | 0 | 3.75 |  | 1155Wa 0000198237 | 0 | - | 0,51 | AllplanAttributes - U-Wert: 0.9; Schallschutzklasse: 32; Sonnenschutztyp: Movable
Fensteröffnung | H2 Ebene +1 | 1155Fen2005704462 | m² | 0 | Fensterarbeiten | Fensteröffnung | 0 | 3.75 |  | 1155Wa 0000198236 | 0 | - | 0,51 | AllplanAttributes - U-Wert: 0.9; Schallschutzklasse: 32; Sonnenschutztyp: Movable
Fensteröffnung | H2 Ebene +1 | 1155Fen0000011957 | m² |  | Wärmedämm-Verbundsysteme | Fensteröffnung |  | 3.75 | NEW | 1155Wa 0000001193 | 0 | - | 0,51 | AllplanAttributes - Material: Fensterelement; Tragendes Bauteil: no; Brandabschnittsdefinierendes Bauteil: no; ash D_Detailverweis: Typ1; ash D_Plannummer: D1726; U-Wert: 0.9; Schallschutzklasse: 32; Sonnenschutztyp: Movable
Fensteröffnung | H2 Ebene +1 | 1155Fen0000011969 | m³ | 0 | Wärmedämm-Verbundsysteme | Fensteröffnung | 0 | 3.75 | NEW | 1155Wa 0000001197 | 0 | - | 0,51 | AllplanAttributes - Material: Fensterelement; Außenliegend: yes; ash D_Detailverweis: Typ1; ash D_Plannummer: D1726; U-Wert: 0.9; Schallschutzklasse: 32; Sonnenschutztyp: Movable
Fensteröffnung | H2 Ebene +1 | 1155Fen0000011971 | m³ | 0 | Wärmedämm-Verbundsysteme | Fensteröffnung | 0 | 3.75 | NEW | 1155Wa 0000001201 | 0 | - | 0,51 | AllplanAttributes - ash D_Detailverweis: Typ1; ash D_Plannummer: D1726; U-Wert: 0.9; Schallschutzklasse: 32; Sonnenschutztyp: Movable
Fensteröffnung | H2 Ebene +1 | 1155Fen0000011973 | m² | 0 | Wärmedämm-Verbundsysteme | Fensteröffnung | 0 | 3.75 | NEW | 1155Wa 0000001205 | 0 | - | 0,51 | AllplanAttributes - ash D_Detailverweis: Typ1; ash D_Plannummer: D1726; U-Wert: 0.9; Schallschutzklasse: 32; Sonnenschutztyp: Movable
Fensteröffnung | H2 Ebene +1 | 1155Fen0000011975 | m² | 0 | Wärmedämm-Verbundsysteme | Fensteröffnung | 0 | 3.75 | NEW | 1155Wa 0000001209 | 0 | - | 0,51 | AllplanAttributes - ash D_Detailverweis: Typ1; ash D_Plannummer: D1726; U-Wert: 0.9; Schallschutzklasse: 32; Sonnenschutztyp: Movable
Fensteröffnung | H2 Ebene +1 | 1155Fen0000011977 | m² | 0 | Wärmedämm-Verbundsysteme | Fensteröffnung | 0 | 3.75 | NEW | 1155Wa 0000001213 | 0 | - | 0,51 | AllplanAttributes - ash D_Detailverweis: Typ1; ash D_Plannummer: D1726; U-Wert: 0.9; Schallschutzklasse: 32; Sonnenschutztyp: Movable
Fensteröffnung | H2 Ebene +1 | 1155Fen0000011979 | m² | 0 | Wärmedämm-Verbundsysteme | Fensteröffnung | 0 | 3.75 | NEW | 1155Wa 0000001217 | 0 | - | 0,51 | AllplanAttributes - ash D_Detailverweis: FS 1; ash D_Plannummer: D780; U-Wert: 0.9; Schallschutzklasse: 32; Sonnenschutztyp: Movable; Bezeichnung: Fensteröffnung
Fensteröffnung | H2 Ebene +1 | 1155Fen0000191863 | m² |  | Fensterarbeiten | Fensteröffnung |  | 3.75 |  | 1155Wa 0000191884 | 0 | - | 0,51 | AllplanAttributes - U-Wert: 0.9; Schallschutzklasse: 32; Sonnenschutztyp: Movable
Fensteröffnung | H2 Ebene +1 | 1155Fen0000191864 | m² | 0 | Fensterarbeiten | Fensteröffnung | 0 | 3.75 |  | 1155Wa 0000191883 | 0 | - | 0,51 | AllplanAttributes - U-Wert: 0.9; Schallschutzklasse: 32; Sonnenschutztyp: Movable
Fensteröffnung | H2 Ebene +1 | 1155Fen0000191865 | m³ | 0 | Fensterarbeiten | Fensteröffnung | 0 | 3.75 |  | 1155Wa 0000191882 | 0 | - | 0,51 | AllplanAttributes - U-Wert: 0.9; Schallschutzklasse: 32; Sonnenschutztyp: Movable
Fensteröffnung | H2 Ebene +1 | 1155Fen0000191866 | m² | 0 | Fensterarbeiten | Fensteröffnung | 0 | 3.75 |  | 1155Wa 0000191881 | 0 | - | 0,51 | AllplanAttributes - U-Wert: 0.9; Schallschutzklasse: 32; Sonnenschutztyp: Movable
Fensteröffnung | H2 Ebene +1 | 1155Fen0000191867 | m² | 0 | Fensterarbeiten | Fensteröffnung | 0 | 3.75 | NEW | 1155Wa 0000191880 | 0 | - | 0,51 | AllplanAttributes - U-Wert: 0.9; Schallschutzklasse: 32; Sonnenschutztyp: Movable
Fensteröffnung | H2 Ebene +1 | 1155Fen0000191868 | m³ | 0 | Fensterarbeiten | Fensteröffnung | 0 | 3.75 | NEW | 1155Wa 0000191879 | 0 | - | 0,51 | AllplanAttributes - U-Wert: 0.9; Schallschutzklasse: 32; Sonnenschutztyp: Movable
Fensteröffnung | H2 Ebene +1 | 1155Fen0000191869 | m² | 0 | Fensterarbeiten | Fensteröffnung | 0 | 3.75 | NEW | 1155Wa 0000191878 | 0 | - | 0,51 | AllplanAttributes - U-Wert: 0.9; Schallschutzklasse: 32; Sonnenschutztyp: Movable
Fensteröffnung | H2 Ebene +1 | 1155Fen0000191870 | m² | 0 | Fensterarbeiten | Fensteröffnung | 0 |  | NEW | 1155Wa 0000191877
Fensteröffnung | H2 Ebene +1 | 1155Fen0000191871 | m² | 0 | Fensterarbeiten | Fensteröffnung | 0 |  | NEW | 1155Wa 0000191876
Fensteröffnung | H2 Ebene +1 | 1155Fen2005776716 | m² | 0 | Trockenbauarbeiten | Fensteröffnung | 0 | 3.75 |  | 1155Wa 0000003947 | 0 | - | 0,51 | AllplanAttributes - U-Wert: 0.9; Schallschutzklasse: 32; Sonnenschutztyp: Movable
Fensteröffnung | H2 Ebene +1 | 1155Fen2005776607 | m² | 0 | Trockenbauarbeiten | Fensteröffnung | 0 | 3.75 |  | 1155Wa 0000003947 | 0 | - | 0,51 | AllplanAttributes - U-Wert: 0.9; Schallschutzklasse: 32; Sonnenschutztyp: Movable
Fensteröffnung | H2 Ebene +1 | 1155Fen2005776453 | m² | 0 | Trockenbauarbeiten | Fensteröffnung | 0 | 3.75 |  | 1155Wa 0000003947 | 0 | - | 0,51 | AllplanAttributes - U-Wert: 0.9; Schallschutzklasse: 32; Sonnenschutztyp: Movable
Fensteröffnung | H2 Ebene +1 | 1155Fen2005822805 | m² | 0 | Fensterarbeiten | Fensteröffnung | 0 | 3.75 |  | 1155Wa 0000003947 | 0 | - | 0,51 | AllplanAttributes - U-Wert: 0.9; Schallschutzklasse: 32; Sonnenschutztyp: Movable
Fensteröffnung | H2 Ebene +1 | 1155Fen2005822804 | m³ | 0 | Fensterarbeiten | Fensteröffnung | 0 | 3.75 |  | 1155Wa 0000003957 | 0 | - | 0,51 | AllplanAttributes - U-Wert: 0.9; Schallschutzklasse: 32; Sonnenschutztyp: Movable
Fensteröffnung | H2 Ebene +1 | 1155Fen2005776452 | m³ | 0 | Fensterarbeiten | Fensteröffnung | 0 | 3.75 |  | 1155Wa 0000003957 | 0 | - | 0,51 | AllplanAttributes - U-Wert: 0.9; Schallschutzklasse: 32; Sonnenschutztyp: Movable
Fensteröffnung | H2 Ebene +1 | 1155Fen2005776606 | m³ | 0 | Fensterarbeiten | Fensteröffnung | 0 | 3.75 |  | 1155Wa 0000003957 | 0 | - | 0,51 | AllplanAttributes - U-Wert: 0.9; Schallschutzklasse: 32; Sonnenschutztyp: Movable
Fensteröffnung | H2 Ebene +1 | 1155Fen2005776715 | m³ | 0 | Fensterarbeiten | Fensteröffnung | 0 | 3.75 |  | 1155Wa 0000003957 | 0 | - | 0,51 | AllplanAttributes - U-Wert: 0.9; Schallschutzklasse: 32; Sonnenschutztyp: Movable
Fensteröffnung | H2 Ebene +1 | 1155Fen2005822803 | m³ | 0 | Fensterarbeiten | Fensteröffnung | 0 | 3.75 |  | 1155Wa 0000003966 | 0 | - | 0,51 | AllplanAttributes - U-Wert: 0.9; Schallschutzklasse: 32; Sonnenschutztyp: Movable
Fensteröffnung | H2 Ebene +1 | 1155Fen2005776451 | m³ | 0 | Fensterarbeiten | Fensteröffnung | 0 | 3.75 |  | 1155Wa 0000003966 | 0 | - | 0,51 | AllplanAttributes - U-Wert: 0.9; Schallschutzklasse: 32; Sonnenschutztyp: Movable
Fensteröffnung | H2 Ebene +1 | 1155Fen2005776605 | m³ | 0 | Fensterarbeiten | Fensteröffnung | 0 | 3.75 |  | 1155Wa 0000003966 | 0 | - | 0,51 | AllplanAttributes - U-Wert: 0.9; Schallschutzklasse: 32; Sonnenschutztyp: Movable
Fensteröffnung | H2 Ebene +1 | 1155Fen2005776714 | m³ | 0 | Fensterarbeiten | Fensteröffnung | 0 | 3.75 |  | 1155Wa 0000003966 | 0 | - | 0,51 | AllplanAttributes - U-Wert: 0.9; Schallschutzklasse: 32; Sonnenschutztyp: Movable
Fensteröffnung | H2 Ebene +1 | 1155Fen2005822802 | m³ | 0 | Fensterarbeiten | Fensteröffnung | 0 | 3.75 |  | 1155Wa 0000003976 | 0 | - | 0,51 | AllplanAttributes - U-Wert: 0.9; Schallschutzklasse: 32; Sonnenschutztyp: Movable
Fensteröffnung | H2 Ebene +1 | 1155Fen2005776450 | m³ | 0 | Fensterarbeiten | Fensteröffnung | 0 | 3.75 |  | 1155Wa 0000003976 | 0 | - | 0,51 | AllplanAttributes - U-Wert: 0.9; Schallschutzklasse: 32; Sonnenschutztyp: Movable
Fensteröffnung | H2 Ebene +1 | 1155Fen2005776604 | m³ | 0 | Fensterarbeiten | Fensteröffnung | 0 | 3.75 |  | 1155Wa 0000003976 | 0 | - | 0,51 | AllplanAttributes - U-Wert: 0.9; Schallschutzklasse: 32; Sonnenschutztyp: Movable
Fensteröffnung | H2 Ebene +1 | 1155Fen2005776713 | m³ | 0 | Fensterarbeiten | Fensteröffnung | 0 | 3.75 |  | 1155Wa 0000003976 | 0 | - | 0,51 | AllplanAttributes - U-Wert: 0.9; Schallschutzklasse: 32; Sonnenschutztyp: Movable
Fensteröffnung | H2 Ebene +1 | 1155Fen2005822801 | m² | 0 | Fensterarbeiten | Fensteröffnung | 0 | 3.75 | NEW | 1155Wa 0000003986 | 0 | - | 0,51 | AllplanAttributes - U-Wert: 0.9; Schallschutzklasse: 32; Sonnenschutztyp: Movable
Fensteröffnung | H2 Ebene +1 | 1155Fen2005776449 | m² | 0 | Fensterarbeiten | Fensteröffnung | 0 | 3.75 | NEW | 1155Wa 0000003986 | 0 | - | 0,51 | AllplanAttributes - U-Wert: 0.9; Schallschutzklasse: 32; Sonnenschutztyp: Movable
Fensteröffnung | H2 Ebene +1 | 1155Fen2005776603 | m² | 0 | Fensterarbeiten | Fensteröffnung | 0 | 3.75 | NEW | 1155Wa 0000003986 | 0 | - | 0,51 | AllplanAttributes - U-Wert: 0.9; Schallschutzklasse: 32; Sonnenschutztyp: Movable
Fensteröffnung | H2 Ebene +1 | 1155Fen2005776712 | m² | 0 | Fensterarbeiten | Fensteröffnung | 0 | 3.75 | NEW | 1155Wa 0000003986 | 0 | - | 0,51 | AllplanAttributes - U-Wert: 0.9; Schallschutzklasse: 32; Sonnenschutztyp: Movable
Fensteröffnung | H2 Ebene +1 | 1155Fen2005822800 | m² | 0 | Fensterarbeiten | Fensteröffnung | 0 | 3.75 | NEW | 1155Wa 0000003996 | 0 | - | 0,51 | AllplanAttributes - U-Wert: 0.9; Schallschutzklasse: 32; Sonnenschutztyp: Movable
Fensteröffnung | H2 Ebene +1 | 1155Fen2005776448 | m² | 0 | Fensterarbeiten | Fensteröffnung | 0 | 3.75 | NEW | 1155Wa 0000003996 | 0 | - | 0,51 | AllplanAttributes - U-Wert: 0.9; Schallschutzklasse: 32; Sonnenschutztyp: Movable
Fensteröffnung | H2 Ebene +1 | 1155Fen2005776602 | m² | 0 | Fensterarbeiten | Fensteröffnung | 0 | 3.75 | NEW | 1155Wa 0000003996 | 0 | - | 0,51 | AllplanAttributes - U-Wert: 0.9; Schallschutzklasse: 32; Sonnenschutztyp: Movable
Fensteröffnung | H2 Ebene +1 | 1155Fen2005776711 | m² | 0 | Fensterarbeiten | Fensteröffnung | 0 | 3.75 | NEW | 1155Wa 0000003996 | 0 | - | 0,51 | AllplanAttributes - U-Wert: 0.9; Schallschutzklasse: 32; Sonnenschutztyp: Movable
Fensteröffnung | H2 Ebene +1 | 1155Fen2005822799 | m² | 0 | Fensterarbeiten | Fensteröffnung | 0 | 3.75 | NEW | 1155Wa 0000004006 | 0 | - | 0,51 | AllplanAttributes - U-Wert: 0.9; Schallschutzklasse: 32; Sonnenschutztyp: Movable
Fensteröffnung | H2 Ebene +1 | 1155Fen2005776447 | m² | 0 | Fensterarbeiten | Fensteröffnung | 0 | 3.75 | NEW | 1155Wa 0000004006 | 0 | - | 0,51 | AllplanAttributes - U-Wert: 0.9; Schallschutzklasse: 32; Sonnenschutztyp: Movable
Fensteröffnung | H2 Ebene +1 | 1155Fen2005776601 | m² | 0 | Fensterarbeiten | Fensteröffnung | 0 | 3.75 | NEW | 1155Wa 0000004006 | 0 | - | 0,51 | AllplanAttributes - U-Wert: 0.9; Schallschutzklasse: 32; Sonnenschutztyp: Movable
Fensteröffnung | H2 Ebene +1 | 1155Fen2005776710 | m² | 0 | Fensterarbeiten | Fensteröffnung | 0 | 3.75 | NEW | 1155Wa 0000004006 | 0 | - | 0,51 | AllplanAttributes - U-Wert: 0.9; Schallschutzklasse: 32; Sonnenschutztyp: Movable
Fensteröffnung | H2 Ebene +1 | 1155Fen2005822798 | m² | 0 | Fensterarbeiten | Fensteröffnung | 0 |  | NEW
Fensteröffnung | H2 Ebene +1 | 1155Fen2005776446 | m² | 0 | Fensterarbeiten | Fensteröffnung | 0 |  | NEW
Fensteröffnung | H2 Ebene +1 | 1155Fen2005776600 | m² | 0 | Fensterarbeiten | Fensteröffnung | 0 |  | NEW
Fensteröffnung | H2 Ebene +1 | 1155Fen2005776709 | m² | 0 | Fensterarbeiten | Fensteröffnung | 0 |  | NEW
Fensteröffnung | H2 Ebene +1 | 1155Fen2005820820 | m² | 0 | Fensterarbeiten | Fensteröffnung | 0 | 3.75 |  | 1155Wa 0000003947 | 0 | - | 0,51 | AllplanAttributes - U-Wert: 0.9; Schallschutzklasse: 32; Sonnenschutztyp: Movable
Fensteröffnung | H2 Ebene +1 | 1155Fen2005776952 | m² | 0 | Fensterarbeiten | Fensteröffnung | 0 | 3.75 |  | 1155Wa 0000003947 | 0 | - | 0,51 | AllplanAttributes - U-Wert: 0.9; Schallschutzklasse: 32; Sonnenschutztyp: Movable
Fensteröffnung | H2 Ebene +1 | 1155Fen2005777056 | m² | 0 | Fensterarbeiten | Fensteröffnung | 0 | 3.75 |  | 1155Wa 0000003947 | 0 | - | 0,51 | AllplanAttributes - U-Wert: 0.9; Schallschutzklasse: 32; Sonnenschutztyp: Movable
Fensteröffnung | H2 Ebene +1 | 1155Fen2005777160 | m² | 0 | Fensterarbeiten | Fensteröffnung | 0 | 3.75 |  | 1155Wa 0000003947 | 0 | - | 0,51 | AllplanAttributes - U-Wert: 0.9; Schallschutzklasse: 32; Sonnenschutztyp: Movable
Fensteröffnung | H2 Ebene +1 | 1155Fen2005820819 | m³ | 0 | Fensterarbeiten | Fensteröffnung | 0 | 3.75 |  | 1155Wa 0000003957 | 0 | - | 0,51 | AllplanAttributes - U-Wert: 0.9; Schallschutzklasse: 32; Sonnenschutztyp: Movable
Fensteröffnung | H2 Ebene +1 | 1155Fen2005776951 | m³ | 0 | Fensterarbeiten | Fensteröffnung | 0 | 3.75 |  | 1155Wa 0000003957 | 0 | - | 0,51 | AllplanAttributes - U-Wert: 0.9; Schallschutzklasse: 32; Sonnenschutztyp: Movable
Fensteröffnung | H2 Ebene +1 | 1155Fen2005777055 | m³ | 0 | Fensterarbeiten | Fensteröffnung | 0 | 3.75 |  | 1155Wa 0000003957 | 0 | - | 0,51 | AllplanAttributes - U-Wert: 0.9; Schallschutzklasse: 32; Sonnenschutztyp: Movable
Fensteröffnung | H2 Ebene +1 | 1155Fen2005777159 | m³ | 0 | Fensterarbeiten | Fensteröffnung | 0 | 3.75 |  | 1155Wa 0000003957 | 0 | - | 0,51 | AllplanAttributes - U-Wert: 0.9; Schallschutzklasse: 32; Sonnenschutztyp: Movable
Fensteröffnung | H2 Ebene +1 | 1155Fen2005820818 | m³ | 0 | Fensterarbeiten | Fensteröffnung | 0 | 3.75 |  | 1155Wa 0000003966 | 0 | - | 0,51 | AllplanAttributes - U-Wert: 0.9; Schallschutzklasse: 32; Sonnenschutztyp: Movable
Fensteröffnung | H2 Ebene +1 | 1155Fen2005776950 | m³ | 0 | Fensterarbeiten | Fensteröffnung | 0 | 3.75 |  | 1155Wa 0000003966 | 0 | - | 0,51 | AllplanAttributes - U-Wert: 0.9; Schallschutzklasse: 32; Sonnenschutztyp: Movable
Fensteröffnung | H2 Ebene +1 | 1155Fen2005777054 | m³ | 0 | Fensterarbeiten | Fensteröffnung | 0 | 3.75 |  | 1155Wa 0000003966 | 0 | - | 0,51 | AllplanAttributes - U-Wert: 0.9; Schallschutzklasse: 32; Sonnenschutztyp: Movable
Fensteröffnung | H2 Ebene +1 | 1155Fen2005777158 | m³ | 0 | Fensterarbeiten | Fensteröffnung | 0 | 3.75 |  | 1155Wa 0000003966 | 0 | - | 0,51 | AllplanAttributes - U-Wert: 0.9; Schallschutzklasse: 32; Sonnenschutztyp: Movable
Fensteröffnung | H2 Ebene +1 | 1155Fen2005820817 | m² | 0 | Fensterarbeiten | Fensteröffnung | 0 | 3.75 |  | 1155Wa 0000003976 | 0 | - | 0,51 | AllplanAttributes - U-Wert: 0.9; Schallschutzklasse: 32; Sonnenschutztyp: Movable
Fensteröffnung | H2 Ebene +1 | 1155Fen2005776949 | m² | 0 | Fensterarbeiten | Fensteröffnung | 0 | 3.75 |  | 1155Wa 0000003976 | 0 | - | 0,51 | AllplanAttributes - U-Wert: 0.9; Schallschutzklasse: 32; Sonnenschutztyp: Movable
Fensteröffnung | H2 Ebene +1 | 1155Fen2005777053 | m² | 0 | Fensterarbeiten | Fensteröffnung | 0 | 3.75 |  | 1155Wa 0000003976 | 0 | - | 0,51 | AllplanAttributes - U-Wert: 0.9; Schallschutzklasse: 32; Sonnenschutztyp: Movable
Fensteröffnung | H2 Ebene +1 | 1155Fen2005777157 | m² | 0 | Fensterarbeiten | Fensteröffnung | 0 | 3.75 |  | 1155Wa 0000003976 | 0 | - | 0,51 | AllplanAttributes - U-Wert: 0.9; Schallschutzklasse: 32; Sonnenschutztyp: Movable
Fensteröffnung | H2 Ebene +1 | 1155Fen2005820816 | m² | 0 | Fensterarbeiten | Fensteröffnung | 0 | 3.75 | NEW | 1155Wa 0000003986 | 0 | - | 0,51 | AllplanAttributes - U-Wert: 0.9; Schallschutzklasse: 32; Sonnenschutztyp: Movable
Fensteröffnung | H2 Ebene +1 | 1155Fen2005776948 | m² | 0 | Fensterarbeiten | Fensteröffnung | 0 | 3.75 | NEW | 1155Wa 0000003986 | 0 | - | 0,51 | AllplanAttributes - U-Wert: 0.9; Schallschutzklasse: 32; Sonnenschutztyp: Movable
Fensteröffnung | H2 Ebene +1 | 1155Fen2005777052 | m² | 0 | Fensterarbeiten | Fensteröffnung | 0 | 3.75 | NEW | 1155Wa 0000003986 | 0 | - | 0,51 | AllplanAttributes - U-Wert: 0.9; Schallschutzklasse: 32; Sonnenschutztyp: Movable
Fensteröffnung | H2 Ebene +1 | 1155Fen2005777156 | m² | 0 | Fensterarbeiten | Fensteröffnung | 0 | 3.75 | NEW | 1155Wa 0000003986 | 0 | - | 0,51 | AllplanAttributes - U-Wert: 0.9; Schallschutzklasse: 32; Sonnenschutztyp: Movable
Fensteröffnung | H2 Ebene +1 | 1155Fen2005820815 | m² | 0 | Fensterarbeiten | Fensteröffnung | 0 | 3.75 | NEW | 1155Wa 0000003996 | 0 | - | 0,51 | AllplanAttributes - U-Wert: 0.9; Schallschutzklasse: 32; Sonnenschutztyp: Movable
Fensteröffnung | H2 Ebene +1 | 1155Fen2005776947 | m² | 0 | Fensterarbeiten | Fensteröffnung | 0 | 3.75 | NEW | 1155Wa 0000003996 | 0 | - | 0,51 | AllplanAttributes - U-Wert: 0.9; Schallschutzklasse: 32; Sonnenschutztyp: Movable
Fensteröffnung | H2 Ebene +1 | 1155Fen2005777051 | m² | 0 | Fensterarbeiten | Fensteröffnung | 0 | 3.75 | NEW | 1155Wa 0000003996 | 0 | - | 0,51 | AllplanAttributes - U-Wert: 0.9; Schallschutzklasse: 32; Sonnenschutztyp: Movable
Fensteröffnung | H2 Ebene +1 | 1155Fen2005777155 | m² | 0 | Fensterarbeiten | Fensteröffnung | 0 | 3.75 | NEW | 1155Wa 0000003996 | 0 | - | 0,51 | AllplanAttributes - U-Wert: 0.9; Schallschutzklasse: 32; Sonnenschutztyp: Movable
Fensteröffnung | H2 Ebene +1 | 1155Fen2005820814 | m² | 0 | Fensterarbeiten | Fensteröffnung | 0 | 3.75 | NEW | 1155Wa 0000004006 | 0 | - | 0,51 | AllplanAttributes - U-Wert: 0.9; Schallschutzklasse: 32; Sonnenschutztyp: Movable
Fensteröffnung | H2 Ebene +1 | 1155Fen2005776946 | m² | 0 | Fensterarbeiten | Fensteröffnung | 0 | 3.75 | NEW | 1155Wa 0000004006 | 0 | - | 0,51 | AllplanAttributes - U-Wert: 0.9; Schallschutzklasse: 32; Sonnenschutztyp: Movable
Fensteröffnung | H2 Ebene +1 | 1155Fen2005777050 | m² | 0 | Fensterarbeiten | Fensteröffnung | 0 | 3.75 | NEW | 1155Wa 0000004006 | 0 | - | 0,51 | AllplanAttributes - U-Wert: 0.9; Schallschutzklasse: 32; Sonnenschutztyp: Movable
Fensteröffnung | H2 Ebene +1 | 1155Fen2005777154 | m² | 0 | Fensterarbeiten | Fensteröffnung | 0 | 3.75 | NEW | 1155Wa 0000004006 | 0 | - | 0,51 | AllplanAttributes - U-Wert: 0.9; Schallschutzklasse: 32; Sonnenschutztyp: Movable
Fensteröffnung | H2 Ebene +1 | 1155Fen2005796690 | m² | 0 | Fensterarbeiten | Fensteröffnung | 0 | 3.75 |  | 1155Wa 0000004655 | 0 | - | 0,51 | AllplanAttributes - U-Wert: 0.9; Schallschutzklasse: 32; Sonnenschutztyp: Movable
Fensteröffnung | H2 Ebene +1 | 1155Fen2005796689 | m³ | 0 | Fensterarbeiten | Fensteröffnung | 0 | 3.75 |  | 1155Wa 0000004651 | 0 | - | 0,51 | AllplanAttributes - U-Wert: 0.9; Schallschutzklasse: 32; Sonnenschutztyp: Movable
Fensteröffnung | H2 Ebene +1 | 1155Fen2005796688 | m³ | 0 | Fensterarbeiten | Fensteröffnung | 0 | 3.75 |  | 1155Wa 0000004647 | 0 | - | 0,51 | AllplanAttributes - U-Wert: 0.9; Schallschutzklasse: 32; Sonnenschutztyp: Movable
Fensteröffnung | H2 Ebene +1 | 1155Fen2005796687 | m² | 0 | Fensterarbeiten | Fensteröffnung | 0 | 3.75 |  | 1155Wa 0000004643 | 0 | - | 0,51 | AllplanAttributes - U-Wert: 0.9; Schallschutzklasse: 32; Sonnenschutztyp: Movable
Fensteröffnung | H2 Ebene +1 | 1155Fen2005796686 | m² | 0 | Fensterarbeiten | Fensteröffnung | 0 | 3.75 | NEW | 1155Wa 0000004639 | 0 | - | 0,51 | AllplanAttributes - U-Wert: 0.9; Schallschutzklasse: 32; Sonnenschutztyp: Movable
Fensteröffnung | H2 Ebene +1 | 1155Fen2005796685 | m² | 0 | Fensterarbeiten | Fensteröffnung | 0 | 3.75 | NEW | 1155Wa 0000004635 | 0 | - | 0,51 | AllplanAttributes - U-Wert: 0.9; Schallschutzklasse: 32; Sonnenschutztyp: Movable
Fensteröffnung | H2 Ebene +1 | 1155Fen2005796684 | m² | 0 | Fensterarbeiten | Fensteröffnung | 0 | 3.75 | NEW | 1155Wa 0000004631 | 0 | - | 0,51 | AllplanAttributes - U-Wert: 0.9; Schallschutzklasse: 32; Sonnenschutztyp: Movable
Fensteröffnung | H2 Ebene +1 | 1155Fen2005779140 | m² | 0 | Fensterarbeiten | Fensteröffnung | 0 | 3.75 |  | 1155Wa 0000004356 | 0 | - | 0,51 | AllplanAttributes - U-Wert: 0.9; Schallschutzklasse: 32; Sonnenschutztyp: Movable
Fensteröffnung | H2 Ebene +1 | 1155Fen2005779139 | m² | 0 | Fensterarbeiten | Fensteröffnung | 0 | 3.75 |  | 1155Wa 0000004360 | 0 | - | 0,51 | AllplanAttributes - U-Wert: 0.9; Schallschutzklasse: 32; Sonnenschutztyp: Movable
Fensteröffnung | H2 Ebene +1 | 1155Fen2005779138 | m³ | 0 | Fensterarbeiten | Fensteröffnung | 0 | 3.75 |  | 1155Wa 0000004364 | 0 | - | 0,51 | AllplanAttributes - U-Wert: 0.9; Schallschutzklasse: 32; Sonnenschutztyp: Movable
Fensteröffnung | H2 Ebene +1 | 1155Fen2005779137 | m² | 0 | Fensterarbeiten | Fensteröffnung | 0 | 3.75 |  | 1155Wa 0000004368 | 0 | - | 0,51 | AllplanAttributes - U-Wert: 0.9; Schallschutzklasse: 32; Sonnenschutztyp: Movable
Fensteröffnung | H2 Ebene +1 | 1155Fen2005779136 | m² | 0 | Fensterarbeiten | Fensteröffnung | 0 | 3.75 | NEW | 1155Wa 0000004372 | 0 | - | 0,51 | AllplanAttributes - U-Wert: 0.9; Schallschutzklasse: 32; Sonnenschutztyp: Movable
Fensteröffnung | H2 Ebene +1 | 1155Fen2005779135 | m³ | 0 | Fensterarbeiten | Fensteröffnung | 0 | 3.75 | NEW | 1155Wa 0000004376 | 0 | - | 0,51 | AllplanAttributes - U-Wert: 0.9; Schallschutzklasse: 32; Sonnenschutztyp: Movable
Fensteröffnung | H2 Ebene +1 | 1155Fen2005779134 | m² | 0 | Fensterarbeiten | Fensteröffnung | 0 | 3.75 | NEW | 1155Wa 0000004380 | 0 | - | 0,51 | AllplanAttributes - U-Wert: 0.9; Schallschutzklasse: 32; Sonnenschutztyp: Movable
Fensteröffnung | H2 Ebene +1 | 1155Fen2005779133 | m² | 0 | Fensterarbeiten | Fensteröffnung | 0 |  | NEW | 1155Wa 0000162482
Fensteröffnung | H2 Ebene +1 | 1155Fen2005779132 | m² | 0 | Fensterarbeiten | Fensteröffnung | 0 |  | NEW | 1155Wa 0000162483
Fensteröffnung | H2 Ebene +1 | 1155Fen2005784972 | m² | 0 | Fensterarbeiten | Fensteröffnung | 0 | 3.75 |  | 1155Wa 0000004865 | 0 | - | 0,51 | AllplanAttributes - U-Wert: 0.9; Schallschutzklasse: 32; Sonnenschutztyp: Movable
Fensteröffnung | H2 Ebene +1 | 1155Fen2005784898 | m² | 0 | Fensterarbeiten | Fensteröffnung | 0 | 3.75 |  | 1155Wa 0000004865 | 0 | - | 0,51 | AllplanAttributes - U-Wert: 0.9; Schallschutzklasse: 32; Sonnenschutztyp: Movable
Fensteröffnung | H2 Ebene +1 | 1155Fen2005784971 | m³ | 0 | Fensterarbeiten | Fensteröffnung | 0 | 3.75 |  | 1155Wa 0000004860 | 0 | - | 0,51 | AllplanAttributes - U-Wert: 0.9; Schallschutzklasse: 32; Sonnenschutztyp: Movable
Fensteröffnung | H2 Ebene +1 | 1155Fen2005784897 | m³ | 0 | Fensterarbeiten | Fensteröffnung | 0 | 3.75 |  | 1155Wa 0000004860 | 0 | - | 0,51 | AllplanAttributes - U-Wert: 0.9; Schallschutzklasse: 32; Sonnenschutztyp: Movable
Fensteröffnung | H2 Ebene +1 | 1155Fen2005784970 | m³ | 0 | Fensterarbeiten | Fensteröffnung | 0 | 3.75 |  | 1155Wa 0000004855 | 0 | - | 0,51 | AllplanAttributes - U-Wert: 0.9; Schallschutzklasse: 32; Sonnenschutztyp: Movable
Fensteröffnung | H2 Ebene +1 | 1155Fen2005784896 | m³ | 0 | Fensterarbeiten | Fensteröffnung | 0 | 3.75 |  | 1155Wa 0000004855 | 0 | - | 0,51 | AllplanAttributes - U-Wert: 0.9; Schallschutzklasse: 32; Sonnenschutztyp: Movable
Fensteröffnung | H2 Ebene +1 | 1155Fen2005784969 | m² | 0 | Fensterarbeiten | Fensteröffnung | 0 | 3.75 |  | 1155Wa 0000004850 | 0 | - | 0,51 | AllplanAttributes - U-Wert: 0.9; Schallschutzklasse: 32; Sonnenschutztyp: Movable
Fensteröffnung | H2 Ebene +1 | 1155Fen2005784895 | m² | 0 | Fensterarbeiten | Fensteröffnung | 0 | 3.75 |  | 1155Wa 0000004850 | 0 | - | 0,51 | AllplanAttributes - U-Wert: 0.9; Schallschutzklasse: 32; Sonnenschutztyp: Movable
Fensteröffnung | H2 Ebene +1 | 1155Fen2005784968 | m² | 0 | Fensterarbeiten | Fensteröffnung | 0 | 3.75 | NEW | 1155Wa 0000004845 | 0 | - | 0,51 | AllplanAttributes - U-Wert: 0.9; Schallschutzklasse: 32; Sonnenschutztyp: Movable
Fensteröffnung | H2 Ebene +1 | 1155Fen2005784894 | m² | 0 | Fensterarbeiten | Fensteröffnung | 0 | 3.75 | NEW | 1155Wa 0000004845 | 0 | - | 0,51 | AllplanAttributes - U-Wert: 0.9; Schallschutzklasse: 32; Sonnenschutztyp: Movable
Fensteröffnung | H2 Ebene +1 | 1155Fen2005784967 | m² | 0 | Fensterarbeiten | Fensteröffnung | 0 | 3.75 | NEW | 1155Wa 0000004840 | 0 | - | 0,51 | AllplanAttributes - U-Wert: 0.9; Schallschutzklasse: 32; Sonnenschutztyp: Movable
Fensteröffnung | H2 Ebene +1 | 1155Fen2005784893 | m² | 0 | Fensterarbeiten | Fensteröffnung | 0 | 3.75 | NEW | 1155Wa 0000004840 | 0 | - | 0,51 | AllplanAttributes - U-Wert: 0.9; Schallschutzklasse: 32; Sonnenschutztyp: Movable
Fensteröffnung | H2 Ebene +1 | 1155Fen2005784966 | m² | 0 | Fensterarbeiten | Fensteröffnung | 0 | 3.75 | NEW | 1155Wa 0000004835 | 0 | - | 0,51 | AllplanAttributes - U-Wert: 0.9; Schallschutzklasse: 32; Sonnenschutztyp: Movable
Fensteröffnung | H2 Ebene +1 | 1155Fen2005784892 | m² | 0 | Fensterarbeiten | Fensteröffnung | 0 | 3.75 | NEW | 1155Wa 0000004835 | 0 | - | 0,51 | AllplanAttributes - U-Wert: 0.9; Schallschutzklasse: 32; Sonnenschutztyp: Movable
Fensteröffnung | H2 Ebene +1 | 1155Fen2005797903 | m² | 0 | Fensterarbeiten | Fensteröffnung | 0 | 3.75 |  | 1155Wa 0000003947 | 0 | - | 0,51 | AllplanAttributes - U-Wert: 0.9; Schallschutzklasse: 32; Sonnenschutztyp: Movable
Fensteröffnung | H2 Ebene +1 | 1155Fen2005798227 | m² | 0 | Fensterarbeiten | Fensteröffnung | 0 | 3.75 |  | 1155Wa 0000003947 | 0 | - | 0,51 | AllplanAttributes - U-Wert: 0.9; Schallschutzklasse: 32; Sonnenschutztyp: Movable
Fensteröffnung | H2 Ebene +1 | 1155Fen2005798494 | m² | 0 | Fensterarbeiten | Fensteröffnung | 0 | 3.75 |  | 1155Wa 0000003947 | 0 | - | 0,51 | AllplanAttributes - U-Wert: 0.9; Schallschutzklasse: 32; Sonnenschutztyp: Movable
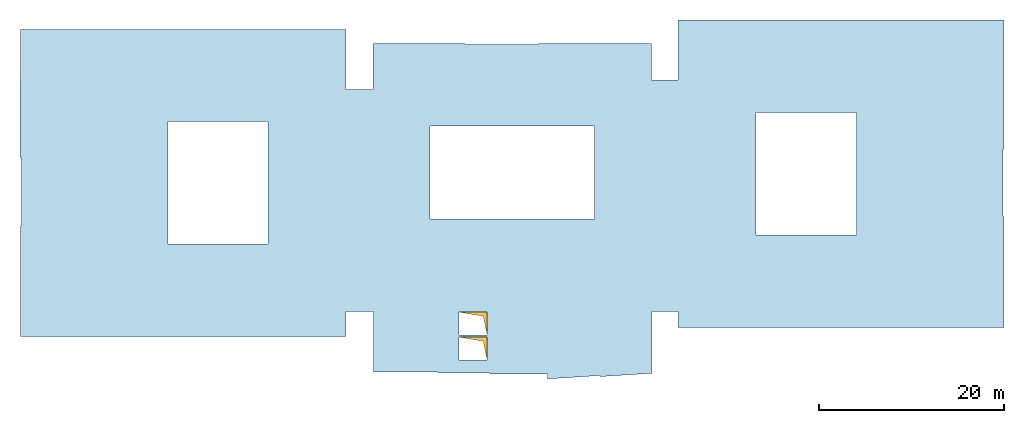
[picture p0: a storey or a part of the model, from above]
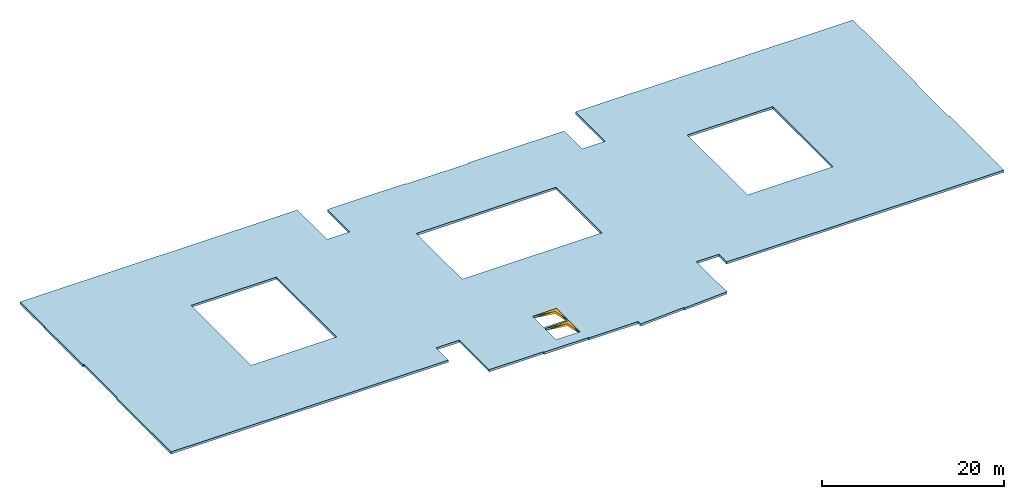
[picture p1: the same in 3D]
Properties of the parts of a building model (IFC4), part 37 of 80

# IfcOpeningElement: Opening (3497)
Name | In | Allright_Bauteil_ID | Abrechnungsart | Versatz_oben | Gewerk | Objektname | Versatz_unten | OKFF | Status | P_ID | AllplanAttributes, Feuerwiderstandsklasse | Sicherheitsklasse | g-Wert
Fensteröffnung | H2 Ebene +1 | 1155Fen2005798316 | m² | 0 | Fensterarbeiten | Fensteröffnung | 0 | 3.75 |  | 1155Wa 0000003947 | 0 | - | 0,51 | AllplanAttributes - U-Wert: 0.9; Schallschutzklasse: 32; Sonnenschutztyp: Movable
Fensteröffnung | H2 Ebene +1 | 1155Fen2005798405 | m² | 0 | Fensterarbeiten | Fensteröffnung | 0 | 3.75 |  | 1155Wa 0000003947 | 0 | - | 0,51 | AllplanAttributes - U-Wert: 0.9; Schallschutzklasse: 32; Sonnenschutztyp: Movable
Fensteröffnung | H2 Ebene +1 | 1155Fen2005797902 | m³ | 0 | Fensterarbeiten | Fensteröffnung | 0 | 3.75 |  | 1155Wa 0000003957 | 0 | - | 0,51 | AllplanAttributes - U-Wert: 0.9; Schallschutzklasse: 32; Sonnenschutztyp: Movable
Fensteröffnung | H2 Ebene +1 | 1155Fen2005798226 | m³ | 0 | Fensterarbeiten | Fensteröffnung | 0 | 3.75 |  | 1155Wa 0000003957 | 0 | - | 0,51 | AllplanAttributes - U-Wert: 0.9; Schallschutzklasse: 32; Sonnenschutztyp: Movable
Fensteröffnung | H2 Ebene +1 | 1155Fen2005798315 | m³ | 0 | Fensterarbeiten | Fensteröffnung | 0 | 3.75 |  | 1155Wa 0000003957 | 0 | - | 0,51 | AllplanAttributes - U-Wert: 0.9; Schallschutzklasse: 32; Sonnenschutztyp: Movable
Fensteröffnung | H2 Ebene +1 | 1155Fen2005798404 | m³ | 0 | Fensterarbeiten | Fensteröffnung | 0 | 3.75 |  | 1155Wa 0000003957 | 0 | - | 0,51 | AllplanAttributes - U-Wert: 0.9; Schallschutzklasse: 32; Sonnenschutztyp: Movable
Fensteröffnung | H2 Ebene +1 | 1155Fen2005798493 | m³ | 0 | Fensterarbeiten | Fensteröffnung | 0 | 3.75 |  | 1155Wa 0000003957 | 0 | - | 0,51 | AllplanAttributes - U-Wert: 0.9; Schallschutzklasse: 32; Sonnenschutztyp: Movable
Fensteröffnung | H2 Ebene +1 | 1155Fen2005797901 | m³ | 0 | Fensterarbeiten | Fensteröffnung | 0 | 3.75 |  | 1155Wa 0000003966 | 0 | - | 0,51 | AllplanAttributes - U-Wert: 0.9; Schallschutzklasse: 32; Sonnenschutztyp: Movable
Fensteröffnung | H2 Ebene +1 | 1155Fen2005798225 | m³ | 0 | Fensterarbeiten | Fensteröffnung | 0 | 3.75 |  | 1155Wa 0000003966 | 0 | - | 0,51 | AllplanAttributes - U-Wert: 0.9; Schallschutzklasse: 32; Sonnenschutztyp: Movable
Fensteröffnung | H2 Ebene +1 | 1155Fen2005798314 | m³ | 0 | Fensterarbeiten | Fensteröffnung | 0 | 3.75 |  | 1155Wa 0000003966 | 0 | - | 0,51 | AllplanAttributes - U-Wert: 0.9; Schallschutzklasse: 32; Sonnenschutztyp: Movable
Fensteröffnung | H2 Ebene +1 | 1155Fen2005798403 | m³ | 0 | Fensterarbeiten | Fensteröffnung | 0 | 3.75 |  | 1155Wa 0000003966 | 0 | - | 0,51 | AllplanAttributes - U-Wert: 0.9; Schallschutzklasse: 32; Sonnenschutztyp: Movable
Fensteröffnung | H2 Ebene +1 | 1155Fen2005798492 | m³ | 0 | Fensterarbeiten | Fensteröffnung | 0 | 3.75 |  | 1155Wa 0000003966 | 0 | - | 0,51 | AllplanAttributes - U-Wert: 0.9; Schallschutzklasse: 32; Sonnenschutztyp: Movable
Fensteröffnung | H2 Ebene +1 | 1155Fen2005797900 | m³ | 0 | Fensterarbeiten | Fensteröffnung | 0 | 3.75 |  | 1155Wa 0000003976 | 0 | - | 0,51 | AllplanAttributes - U-Wert: 0.9; Schallschutzklasse: 32; Sonnenschutztyp: Movable
Fensteröffnung | H2 Ebene +1 | 1155Fen2005798224 | m³ | 0 | Fensterarbeiten | Fensteröffnung | 0 | 3.75 |  | 1155Wa 0000003976 | 0 | - | 0,51 | AllplanAttributes - U-Wert: 0.9; Schallschutzklasse: 32; Sonnenschutztyp: Movable
Fensteröffnung | H2 Ebene +1 | 1155Fen2005798313 | m³ | 0 | Fensterarbeiten | Fensteröffnung | 0 | 3.75 |  | 1155Wa 0000003976 | 0 | - | 0,51 | AllplanAttributes - U-Wert: 0.9; Schallschutzklasse: 32; Sonnenschutztyp: Movable
Fensteröffnung | H2 Ebene +1 | 1155Fen2005798402 | m³ | 0 | Fensterarbeiten | Fensteröffnung | 0 | 3.75 |  | 1155Wa 0000003976 | 0 | - | 0,51 | AllplanAttributes - U-Wert: 0.9; Schallschutzklasse: 32; Sonnenschutztyp: Movable
Fensteröffnung | H2 Ebene +1 | 1155Fen2005798491 | m³ | 0 | Fensterarbeiten | Fensteröffnung | 0 | 3.75 |  | 1155Wa 0000003976 | 0 | - | 0,51 | AllplanAttributes - U-Wert: 0.9; Schallschutzklasse: 32; Sonnenschutztyp: Movable
Fensteröffnung | H2 Ebene +1 | 1155Fen2005797899 | m² | 0 | Fensterarbeiten | Fensteröffnung | 0 | 3.75 | NEW | 1155Wa 0000003986 | 0 | - | 0,51 | AllplanAttributes - U-Wert: 0.9; Schallschutzklasse: 32; Sonnenschutztyp: Movable
Fensteröffnung | H2 Ebene +1 | 1155Fen2005798223 | m² | 0 | Fensterarbeiten | Fensteröffnung | 0 | 3.75 | NEW | 1155Wa 0000003986 | 0 | - | 0,51 | AllplanAttributes - U-Wert: 0.9; Schallschutzklasse: 32; Sonnenschutztyp: Movable
Fensteröffnung | H2 Ebene +1 | 1155Fen2005798312 | m² | 0 | Fensterarbeiten | Fensteröffnung | 0 | 3.75 | NEW | 1155Wa 0000003986 | 0 | - | 0,51 | AllplanAttributes - U-Wert: 0.9; Schallschutzklasse: 32; Sonnenschutztyp: Movable
Fensteröffnung | H2 Ebene +1 | 1155Fen2005798401 | m² | 0 | Fensterarbeiten | Fensteröffnung | 0 | 3.75 | NEW | 1155Wa 0000003986 | 0 | - | 0,51 | AllplanAttributes - U-Wert: 0.9; Schallschutzklasse: 32; Sonnenschutztyp: Movable
Fensteröffnung | H2 Ebene +1 | 1155Fen2005798490 | m² | 0 | Fensterarbeiten | Fensteröffnung | 0 | 3.75 | NEW | 1155Wa 0000003986 | 0 | - | 0,51 | AllplanAttributes - U-Wert: 0.9; Schallschutzklasse: 32; Sonnenschutztyp: Movable
Fensteröffnung | H2 Ebene +1 | 1155Fen2005797898 | m² | 0 | Fensterarbeiten | Fensteröffnung | 0 | 3.75 | NEW | 1155Wa 0000003996 | 0 | - | 0,51 | AllplanAttributes - U-Wert: 0.9; Schallschutzklasse: 32; Sonnenschutztyp: Movable
Fensteröffnung | H2 Ebene +1 | 1155Fen2005798222 | m² | 0 | Fensterarbeiten | Fensteröffnung | 0 | 3.75 | NEW | 1155Wa 0000003996 | 0 | - | 0,51 | AllplanAttributes - U-Wert: 0.9; Schallschutzklasse: 32; Sonnenschutztyp: Movable
Fensteröffnung | H2 Ebene +1 | 1155Fen2005798311 | m² | 0 | Fensterarbeiten | Fensteröffnung | 0 | 3.75 | NEW | 1155Wa 0000003996 | 0 | - | 0,51 | AllplanAttributes - U-Wert: 0.9; Schallschutzklasse: 32; Sonnenschutztyp: Movable
Fensteröffnung | H2 Ebene +1 | 1155Fen2005798400 | m² | 0 | Fensterarbeiten | Fensteröffnung | 0 | 3.75 | NEW | 1155Wa 0000003996 | 0 | - | 0,51 | AllplanAttributes - U-Wert: 0.9; Schallschutzklasse: 32; Sonnenschutztyp: Movable
Fensteröffnung | H2 Ebene +1 | 1155Fen2005798489 | m² | 0 | Fensterarbeiten | Fensteröffnung | 0 | 3.75 | NEW | 1155Wa 0000003996 | 0 | - | 0,51 | AllplanAttributes - U-Wert: 0.9; Schallschutzklasse: 32; Sonnenschutztyp: Movable
Fensteröffnung | H2 Ebene +1 | 1155Fen2005797897 | m² | 0 | Fensterarbeiten | Fensteröffnung | 0 | 3.75 | NEW | 1155Wa 0000004006 | 0 | - | 0,51 | AllplanAttributes - U-Wert: 0.9; Schallschutzklasse: 32; Sonnenschutztyp: Movable
Fensteröffnung | H2 Ebene +1 | 1155Fen2005798221 | m² | 0 | Fensterarbeiten | Fensteröffnung | 0 | 3.75 | NEW | 1155Wa 0000004006 | 0 | - | 0,51 | AllplanAttributes - U-Wert: 0.9; Schallschutzklasse: 32; Sonnenschutztyp: Movable
Fensteröffnung | H2 Ebene +1 | 1155Fen2005798310 | m² | 0 | Fensterarbeiten | Fensteröffnung | 0 | 3.75 | NEW | 1155Wa 0000004006 | 0 | - | 0,51 | AllplanAttributes - U-Wert: 0.9; Schallschutzklasse: 32; Sonnenschutztyp: Movable
Fensteröffnung | H2 Ebene +1 | 1155Fen2005798399 | m² | 0 | Fensterarbeiten | Fensteröffnung | 0 | 3.75 | NEW | 1155Wa 0000004006 | 0 | - | 0,51 | AllplanAttributes - U-Wert: 0.9; Schallschutzklasse: 32; Sonnenschutztyp: Movable
Fensteröffnung | H2 Ebene +1 | 1155Fen2005798488 | m² | 0 | Fensterarbeiten | Fensteröffnung | 0 | 3.75 | NEW | 1155Wa 0000004006 | 0 | - | 0,51 | AllplanAttributes - U-Wert: 0.9; Schallschutzklasse: 32; Sonnenschutztyp: Movable
Fensteröffnung | H2 Ebene +1 | 1155Fen2005797896 | m² | 0 | Fensterarbeiten | Fensteröffnung | 0 |  | NEW
Fensteröffnung | H2 Ebene +1 | 1155Fen2005798220 | m² | 0 | Fensterarbeiten | Fensteröffnung | 0 |  | NEW
Fensteröffnung | H2 Ebene +1 | 1155Fen2005798309 | m² | 0 | Fensterarbeiten | Fensteröffnung | 0 |  | NEW
Fensteröffnung | H2 Ebene +1 | 1155Fen2005798398 | m² | 0 | Fensterarbeiten | Fensteröffnung | 0 |  | NEW
Fensteröffnung | H2 Ebene +1 | 1155Fen2005798487 | m² | 0 | Fensterarbeiten | Fensteröffnung | 0 |  | NEW
Fensteröffnung | H2 Ebene +1 | 1155Fen2005802041 | m² | 0 | Fensterarbeiten | Fensteröffnung | 0 | 3.75 |  | 1155Wa 0000005300 | 0 | - | 0,51 | AllplanAttributes - U-Wert: 0.9; Schallschutzklasse: 32; Sonnenschutztyp: Movable
Fensteröffnung | H2 Ebene +1 | 1155Fen2005802384 | m² | 0 | Fensterarbeiten | Fensteröffnung | 0 | 3.75 |  | 1155Wa 0000005300 | 0 | - | 0,51 | AllplanAttributes - U-Wert: 0.9; Schallschutzklasse: 32; Sonnenschutztyp: Movable
Fensteröffnung | H2 Ebene +1 | 1155Fen2005802711 | m² | 0 | Fensterarbeiten | Fensteröffnung | 0 | 3.75 |  | 1155Wa 0000005300 | 0 | - | 0,51 | AllplanAttributes - U-Wert: 0.9; Schallschutzklasse: 32; Sonnenschutztyp: Movable
Fensteröffnung | H2 Ebene +1 | 1155Fen2005802617 | m² | 0 | Fensterarbeiten | Fensteröffnung | 0 | 3.75 |  | 1155Wa 0000005300 | 0 | - | 0,51 | AllplanAttributes - U-Wert: 0.9; Schallschutzklasse: 32; Sonnenschutztyp: Movable
Fensteröffnung | H2 Ebene +1 | 1155Fen2005802523 | m² | 0 | Fensterarbeiten | Fensteröffnung | 0 | 3.75 |  | 1155Wa 0000005300 | 0 | - | 0,51 | AllplanAttributes - U-Wert: 0.9; Schallschutzklasse: 32; Sonnenschutztyp: Movable
Fensteröffnung | H2 Ebene +1 | 1155Fen2005802522 | m³ | 0 | Fensterarbeiten | Fensteröffnung | 0 | 3.75 |  | 1155Wa 0000005290 | 0 | - | 0,51 | AllplanAttributes - U-Wert: 0.9; Schallschutzklasse: 32; Sonnenschutztyp: Movable
Fensteröffnung | H2 Ebene +1 | 1155Fen2005802616 | m³ | 0 | Fensterarbeiten | Fensteröffnung | 0 | 3.75 |  | 1155Wa 0000005290 | 0 | - | 0,51 | AllplanAttributes - U-Wert: 0.9; Schallschutzklasse: 32; Sonnenschutztyp: Movable
Fensteröffnung | H2 Ebene +1 | 1155Fen2005802710 | m³ | 0 | Fensterarbeiten | Fensteröffnung | 0 | 3.75 |  | 1155Wa 0000005290 | 0 | - | 0,51 | AllplanAttributes - U-Wert: 0.9; Schallschutzklasse: 32; Sonnenschutztyp: Movable
Fensteröffnung | H2 Ebene +1 | 1155Fen2005802383 | m³ | 0 | Fensterarbeiten | Fensteröffnung | 0 | 3.75 |  | 1155Wa 0000005290 | 0 | - | 0,51 | AllplanAttributes - U-Wert: 0.9; Schallschutzklasse: 32; Sonnenschutztyp: Movable
Fensteröffnung | H2 Ebene +1 | 1155Fen2005802040 | m³ | 0 | Fensterarbeiten | Fensteröffnung | 0 | 3.75 |  | 1155Wa 0000005290 | 0 | - | 0,51 | AllplanAttributes - U-Wert: 0.9; Schallschutzklasse: 32; Sonnenschutztyp: Movable
Fensteröffnung | H2 Ebene +1 | 1155Fen2005802521 | m³ | 0 | Fensterarbeiten | Fensteröffnung | 0 | 3.75 |  | 1155Wa 0000005280 | 0 | - | 0,51 | AllplanAttributes - U-Wert: 0.9; Schallschutzklasse: 32; Sonnenschutztyp: Movable
Fensteröffnung | H2 Ebene +1 | 1155Fen2005802615 | m³ | 0 | Fensterarbeiten | Fensteröffnung | 0 | 3.75 |  | 1155Wa 0000005280 | 0 | - | 0,51 | AllplanAttributes - U-Wert: 0.9; Schallschutzklasse: 32; Sonnenschutztyp: Movable
Fensteröffnung | H2 Ebene +1 | 1155Fen2005802709 | m³ | 0 | Fensterarbeiten | Fensteröffnung | 0 | 3.75 |  | 1155Wa 0000005280 | 0 | - | 0,51 | AllplanAttributes - U-Wert: 0.9; Schallschutzklasse: 32; Sonnenschutztyp: Movable
Fensteröffnung | H2 Ebene +1 | 1155Fen2005802382 | m³ | 0 | Fensterarbeiten | Fensteröffnung | 0 | 3.75 |  | 1155Wa 0000005280 | 0 | - | 0,51 | AllplanAttributes - U-Wert: 0.9; Schallschutzklasse: 32; Sonnenschutztyp: Movable
Fensteröffnung | H2 Ebene +1 | 1155Fen2005802039 | m³ | 0 | Fensterarbeiten | Fensteröffnung | 0 | 3.75 |  | 1155Wa 0000005280 | 0 | - | 0,51 | AllplanAttributes - U-Wert: 0.9; Schallschutzklasse: 32; Sonnenschutztyp: Movable
Fensteröffnung | H2 Ebene +1 | 1155Fen2005802520 | m² | 0 | Fensterarbeiten | Fensteröffnung | 0 | 3.75 |  | 1155Wa 0000005270 | 0 | - | 0,51 | AllplanAttributes - U-Wert: 0.9; Schallschutzklasse: 32; Sonnenschutztyp: Movable
Fensteröffnung | H2 Ebene +1 | 1155Fen2005802614 | m² | 0 | Fensterarbeiten | Fensteröffnung | 0 | 3.75 |  | 1155Wa 0000005270 | 0 | - | 0,51 | AllplanAttributes - U-Wert: 0.9; Schallschutzklasse: 32; Sonnenschutztyp: Movable
Fensteröffnung | H2 Ebene +1 | 1155Fen2005802708 | m² | 0 | Fensterarbeiten | Fensteröffnung | 0 | 3.75 |  | 1155Wa 0000005270 | 0 | - | 0,51 | AllplanAttributes - U-Wert: 0.9; Schallschutzklasse: 32; Sonnenschutztyp: Movable
Fensteröffnung | H2 Ebene +1 | 1155Fen2005802381 | m² | 0 | Fensterarbeiten | Fensteröffnung | 0 | 3.75 |  | 1155Wa 0000005270 | 0 | - | 0,51 | AllplanAttributes - U-Wert: 0.9; Schallschutzklasse: 32; Sonnenschutztyp: Movable
Fensteröffnung | H2 Ebene +1 | 1155Fen2005802038 | m² | 0 | Fensterarbeiten | Fensteröffnung | 0 | 3.75 |  | 1155Wa 0000005270 | 0 | - | 0,51 | AllplanAttributes - U-Wert: 0.9; Schallschutzklasse: 32; Sonnenschutztyp: Movable
Fensteröffnung | H2 Ebene +1 | 1155Fen2005802519 | m² | 0 | Fensterarbeiten | Fensteröffnung | 0 | 3.75 | NEW | 1155Wa 0000005260 | 0 | - | 0,51 | AllplanAttributes - U-Wert: 0.9; Schallschutzklasse: 32; Sonnenschutztyp: Movable
Fensteröffnung | H2 Ebene +1 | 1155Fen2005802613 | m² | 0 | Fensterarbeiten | Fensteröffnung | 0 | 3.75 | NEW | 1155Wa 0000005260 | 0 | - | 0,51 | AllplanAttributes - U-Wert: 0.9; Schallschutzklasse: 32; Sonnenschutztyp: Movable
Fensteröffnung | H2 Ebene +1 | 1155Fen2005802707 | m² | 0 | Fensterarbeiten | Fensteröffnung | 0 | 3.75 | NEW | 1155Wa 0000005260 | 0 | - | 0,51 | AllplanAttributes - U-Wert: 0.9; Schallschutzklasse: 32; Sonnenschutztyp: Movable
Fensteröffnung | H2 Ebene +1 | 1155Fen2005802380 | m² | 0 | Fensterarbeiten | Fensteröffnung | 0 | 3.75 | NEW | 1155Wa 0000005260 | 0 | - | 0,51 | AllplanAttributes - U-Wert: 0.9; Schallschutzklasse: 32; Sonnenschutztyp: Movable
Fensteröffnung | H2 Ebene +1 | 1155Fen2005802037 | m² | 0 | Fensterarbeiten | Fensteröffnung | 0 | 3.75 | NEW | 1155Wa 0000005260 | 0 | - | 0,51 | AllplanAttributes - U-Wert: 0.9; Schallschutzklasse: 32; Sonnenschutztyp: Movable
Fensteröffnung | H2 Ebene +1 | 1155Fen2005802518 | m² | 0 | Fensterarbeiten | Fensteröffnung | 0 | 3.75 | NEW | 1155Wa 0000005250 | 0 | - | 0,51 | AllplanAttributes - U-Wert: 0.9; Schallschutzklasse: 32; Sonnenschutztyp: Movable
Fensteröffnung | H2 Ebene +1 | 1155Fen2005802612 | m² | 0 | Fensterarbeiten | Fensteröffnung | 0 | 3.75 | NEW | 1155Wa 0000005250 | 0 | - | 0,51 | AllplanAttributes - U-Wert: 0.9; Schallschutzklasse: 32; Sonnenschutztyp: Movable
Fensteröffnung | H2 Ebene +1 | 1155Fen2005802706 | m² | 0 | Fensterarbeiten | Fensteröffnung | 0 | 3.75 | NEW | 1155Wa 0000005250 | 0 | - | 0,51 | AllplanAttributes - U-Wert: 0.9; Schallschutzklasse: 32; Sonnenschutztyp: Movable
Fensteröffnung | H2 Ebene +1 | 1155Fen2005802379 | m² | 0 | Fensterarbeiten | Fensteröffnung | 0 | 3.75 | NEW | 1155Wa 0000005250 | 0 | - | 0,51 | AllplanAttributes - U-Wert: 0.9; Schallschutzklasse: 32; Sonnenschutztyp: Movable
Fensteröffnung | H2 Ebene +1 | 1155Fen2005802036 | m² | 0 | Fensterarbeiten | Fensteröffnung | 0 | 3.75 | NEW | 1155Wa 0000005250 | 0 | - | 0,51 | AllplanAttributes - U-Wert: 0.9; Schallschutzklasse: 32; Sonnenschutztyp: Movable
Fensteröffnung | H2 Ebene +1 | 1155Fen2005802517 | m² | 0 | Fensterarbeiten | Fensteröffnung | 0 | 3.75 | NEW | 1155Wa 0000005240 | 0 | - | 0,51 | AllplanAttributes - U-Wert: 0.9; Schallschutzklasse: 32; Sonnenschutztyp: Movable
Fensteröffnung | H2 Ebene +1 | 1155Fen2005802611 | m² | 0 | Fensterarbeiten | Fensteröffnung | 0 | 3.75 | NEW | 1155Wa 0000005240 | 0 | - | 0,51 | AllplanAttributes - U-Wert: 0.9; Schallschutzklasse: 32; Sonnenschutztyp: Movable
Fensteröffnung | H2 Ebene +1 | 1155Fen2005802705 | m² | 0 | Fensterarbeiten | Fensteröffnung | 0 | 3.75 | NEW | 1155Wa 0000005240 | 0 | - | 0,51 | AllplanAttributes - U-Wert: 0.9; Schallschutzklasse: 32; Sonnenschutztyp: Movable
Fensteröffnung | H2 Ebene +1 | 1155Fen2005802378 | m² | 0 | Fensterarbeiten | Fensteröffnung | 0 | 3.75 | NEW | 1155Wa 0000005240 | 0 | - | 0,51 | AllplanAttributes - U-Wert: 0.9; Schallschutzklasse: 32; Sonnenschutztyp: Movable
Fensteröffnung | H2 Ebene +1 | 1155Fen2005802035 | m² | 0 | Fensterarbeiten | Fensteröffnung | 0 | 3.75 | NEW | 1155Wa 0000005240 | 0 | - | 0,51 | AllplanAttributes - U-Wert: 0.9; Schallschutzklasse: 32; Sonnenschutztyp: Movable
Fensteröffnung | H2 Ebene +1 | 1155Fen2005800300 | m² | 0 | Fensterarbeiten | Fensteröffnung | 0 | 3.75 |  | 1155Wa 0000003947 | 0 | - | 0,51 | AllplanAttributes - U-Wert: 0.9; Schallschutzklasse: 32; Sonnenschutztyp: Movable
Fensteröffnung | H2 Ebene +1 | 1155Fen2005800496 | m² | 0 | Fensterarbeiten | Fensteröffnung | 0 | 3.75 |  | 1155Wa 0000003947 | 0 | - | 0,51 | AllplanAttributes - U-Wert: 0.9; Schallschutzklasse: 32; Sonnenschutztyp: Movable
Fensteröffnung | H2 Ebene +1 | 1155Fen2005800605 | m² | 0 | Fensterarbeiten | Fensteröffnung | 0 | 3.75 |  | 1155Wa 0000003947 | 0 | - | 0,51 | AllplanAttributes - U-Wert: 0.9; Schallschutzklasse: 32; Sonnenschutztyp: Movable
Fensteröffnung | H2 Ebene +1 | 1155Fen2005800191 | m² | 0 | Fensterarbeiten | Fensteröffnung | 0 | 3.75 |  | 1155Wa 0000003947 | 0 | - | 0,51 | AllplanAttributes - U-Wert: 0.9; Schallschutzklasse: 32; Sonnenschutztyp: Movable
Fensteröffnung | H2 Ebene +1 | 1155Fen2005800299 | m³ | 0 | Fensterarbeiten | Fensteröffnung | 0 | 3.75 |  | 1155Wa 0000003957 | 0 | - | 0,51 | AllplanAttributes - U-Wert: 0.9; Schallschutzklasse: 32; Sonnenschutztyp: Movable
Fensteröffnung | H2 Ebene +1 | 1155Fen2005800495 | m³ | 0 | Fensterarbeiten | Fensteröffnung | 0 | 3.75 |  | 1155Wa 0000003957 | 0 | - | 0,51 | AllplanAttributes - U-Wert: 0.9; Schallschutzklasse: 32; Sonnenschutztyp: Movable
Fensteröffnung | H2 Ebene +1 | 1155Fen2005800604 | m³ | 0 | Fensterarbeiten | Fensteröffnung | 0 | 3.75 |  | 1155Wa 0000003957 | 0 | - | 0,51 | AllplanAttributes - U-Wert: 0.9; Schallschutzklasse: 32; Sonnenschutztyp: Movable
Fensteröffnung | H2 Ebene +1 | 1155Fen2005800190 | m³ | 0 | Fensterarbeiten | Fensteröffnung | 0 | 3.75 |  | 1155Wa 0000003957 | 0 | - | 0,51 | AllplanAttributes - U-Wert: 0.9; Schallschutzklasse: 32; Sonnenschutztyp: Movable
Fensteröffnung | H2 Ebene +1 | 1155Fen2005800298 | m³ | 0 | Fensterarbeiten | Fensteröffnung | 0 | 3.75 |  | 1155Wa 0000003966 | 0 | - | 0,51 | AllplanAttributes - U-Wert: 0.9; Schallschutzklasse: 32; Sonnenschutztyp: Movable
Fensteröffnung | H2 Ebene +1 | 1155Fen2005800494 | m³ | 0 | Fensterarbeiten | Fensteröffnung | 0 | 3.75 |  | 1155Wa 0000003966 | 0 | - | 0,51 | AllplanAttributes - U-Wert: 0.9; Schallschutzklasse: 32; Sonnenschutztyp: Movable
Fensteröffnung | H2 Ebene +1 | 1155Fen2005800603 | m³ | 0 | Fensterarbeiten | Fensteröffnung | 0 | 3.75 |  | 1155Wa 0000003966 | 0 | - | 0,51 | AllplanAttributes - U-Wert: 0.9; Schallschutzklasse: 32; Sonnenschutztyp: Movable
Fensteröffnung | H2 Ebene +1 | 1155Fen2005800189 | m³ | 0 | Fensterarbeiten | Fensteröffnung | 0 | 3.75 |  | 1155Wa 0000003966 | 0 | - | 0,51 | AllplanAttributes - U-Wert: 0.9; Schallschutzklasse: 32; Sonnenschutztyp: Movable
Fensteröffnung | H2 Ebene +1 | 1155Fen2005800297 | m³ | 0 | Fensterarbeiten | Fensteröffnung | 0 | 3.75 |  | 1155Wa 0000003976 | 0 | - | 0,51 | AllplanAttributes - U-Wert: 0.9; Schallschutzklasse: 32; Sonnenschutztyp: Movable
Fensteröffnung | H2 Ebene +1 | 1155Fen2005800493 | m³ | 0 | Fensterarbeiten | Fensteröffnung | 0 | 3.75 |  | 1155Wa 0000003976 | 0 | - | 0,51 | AllplanAttributes - U-Wert: 0.9; Schallschutzklasse: 32; Sonnenschutztyp: Movable
Fensteröffnung | H2 Ebene +1 | 1155Fen2005800602 | m³ | 0 | Fensterarbeiten | Fensteröffnung | 0 | 3.75 |  | 1155Wa 0000003976 | 0 | - | 0,51 | AllplanAttributes - U-Wert: 0.9; Schallschutzklasse: 32; Sonnenschutztyp: Movable
Fensteröffnung | H2 Ebene +1 | 1155Fen2005800188 | m³ | 0 | Fensterarbeiten | Fensteröffnung | 0 | 3.75 |  | 1155Wa 0000003976 | 0 | - | 0,51 | AllplanAttributes - U-Wert: 0.9; Schallschutzklasse: 32; Sonnenschutztyp: Movable
Fensteröffnung | H2 Ebene +1 | 1155Fen2005800296 | m² | 0 | Fensterarbeiten | Fensteröffnung | 0 | 3.75 | NEW | 1155Wa 0000003986 | 0 | - | 0,51 | AllplanAttributes - U-Wert: 0.9; Schallschutzklasse: 32; Sonnenschutztyp: Movable
Fensteröffnung | H2 Ebene +1 | 1155Fen2005800492 | m² | 0 | Fensterarbeiten | Fensteröffnung | 0 | 3.75 | NEW | 1155Wa 0000003986 | 0 | - | 0,51 | AllplanAttributes - U-Wert: 0.9; Schallschutzklasse: 32; Sonnenschutztyp: Movable
Fensteröffnung | H2 Ebene +1 | 1155Fen2005800601 | m² | 0 | Fensterarbeiten | Fensteröffnung | 0 | 3.75 | NEW | 1155Wa 0000003986 | 0 | - | 0,51 | AllplanAttributes - U-Wert: 0.9; Schallschutzklasse: 32; Sonnenschutztyp: Movable
Fensteröffnung | H2 Ebene +1 | 1155Fen2005800187 | m² | 0 | Fensterarbeiten | Fensteröffnung | 0 | 3.75 | NEW | 1155Wa 0000003986 | 0 | - | 0,51 | AllplanAttributes - U-Wert: 0.9; Schallschutzklasse: 32; Sonnenschutztyp: Movable
Fensteröffnung | H2 Ebene +1 | 1155Fen2005800295 | m² | 0 | Fensterarbeiten | Fensteröffnung | 0 | 3.75 | NEW | 1155Wa 0000003996 | 0 | - | 0,51 | AllplanAttributes - U-Wert: 0.9; Schallschutzklasse: 32; Sonnenschutztyp: Movable
Fensteröffnung | H2 Ebene +1 | 1155Fen2005800491 | m² | 0 | Fensterarbeiten | Fensteröffnung | 0 | 3.75 | NEW | 1155Wa 0000003996 | 0 | - | 0,51 | AllplanAttributes - U-Wert: 0.9; Schallschutzklasse: 32; Sonnenschutztyp: Movable
Fensteröffnung | H2 Ebene +1 | 1155Fen2005800600 | m² | 0 | Fensterarbeiten | Fensteröffnung | 0 | 3.75 | NEW | 1155Wa 0000003996 | 0 | - | 0,51 | AllplanAttributes - U-Wert: 0.9; Schallschutzklasse: 32; Sonnenschutztyp: Movable
Fensteröffnung | H2 Ebene +1 | 1155Fen2005800186 | m² | 0 | Fensterarbeiten | Fensteröffnung | 0 | 3.75 | NEW | 1155Wa 0000003996 | 0 | - | 0,51 | AllplanAttributes - U-Wert: 0.9; Schallschutzklasse: 32; Sonnenschutztyp: Movable
Fensteröffnung | H2 Ebene +1 | 1155Fen2005800294 | m² | 0 | Fensterarbeiten | Fensteröffnung | 0 | 3.75 | NEW | 1155Wa 0000004006 | 0 | - | 0,51 | AllplanAttributes - U-Wert: 0.9; Schallschutzklasse: 32; Sonnenschutztyp: Movable
Fensteröffnung | H2 Ebene +1 | 1155Fen2005800490 | m² | 0 | Fensterarbeiten | Fensteröffnung | 0 | 3.75 | NEW | 1155Wa 0000004006 | 0 | - | 0,51 | AllplanAttributes - U-Wert: 0.9; Schallschutzklasse: 32; Sonnenschutztyp: Movable
Fensteröffnung | H2 Ebene +1 | 1155Fen2005800599 | m² | 0 | Fensterarbeiten | Fensteröffnung | 0 | 3.75 | NEW | 1155Wa 0000004006 | 0 | - | 0,51 | AllplanAttributes - U-Wert: 0.9; Schallschutzklasse: 32; Sonnenschutztyp: Movable
Fensteröffnung | H2 Ebene +1 | 1155Fen2005800185 | m² | 0 | Fensterarbeiten | Fensteröffnung | 0 | 3.75 | NEW | 1155Wa 0000004006 | 0 | - | 0,51 | AllplanAttributes - U-Wert: 0.9; Schallschutzklasse: 32; Sonnenschutztyp: Movable
Fensteröffnung | H2 Ebene +1 | 1155Fen2005800293 | m² | 0 | Fensterarbeiten | Fensteröffnung | 0 |  | NEW
Fensteröffnung | H2 Ebene +1 | 1155Fen2005800489 | m² | 0 | Fensterarbeiten | Fensteröffnung | 0 |  | NEW
Fensteröffnung | H2 Ebene +1 | 1155Fen2005800598 | m² | 0 | Fensterarbeiten | Fensteröffnung | 0 |  | NEW
Fensteröffnung | H2 Ebene +1 | 1155Fen2005800184 | m² | 0 | Fensterarbeiten | Fensteröffnung | 0 |  | NEW
Fensteröffnung | H2 Ebene +1 | 1155Fen2005804228 | m² | 0 | Fensterarbeiten | Fensteröffnung | 0 | 3.75 |  | 1155Wa 0000005300 | 0 | - | 0,51 | AllplanAttributes - U-Wert: 0.9; Schallschutzklasse: 32; Sonnenschutztyp: Movable
Fensteröffnung | H2 Ebene +1 | 1155Fen2005804124 | m² | 0 | Fensterarbeiten | Fensteröffnung | 0 | 3.75 |  | 1155Wa 0000005300 | 0 | - | 0,51 | AllplanAttributes - U-Wert: 0.9; Schallschutzklasse: 32; Sonnenschutztyp: Movable
Fensteröffnung | H2 Ebene +1 | 1155Fen2005804020 | m² | 0 | Fensterarbeiten | Fensteröffnung | 0 | 3.75 |  | 1155Wa 0000005300 | 0 | - | 0,51 | AllplanAttributes - U-Wert: 0.9; Schallschutzklasse: 32; Sonnenschutztyp: Movable
Fensteröffnung | H2 Ebene +1 | 1155Fen2005804332 | m² | 0 | Fensterarbeiten | Fensteröffnung | 0 | 3.75 |  | 1155Wa 0000005300 | 0 | - | 0,51 | AllplanAttributes - U-Wert: 0.9; Schallschutzklasse: 32; Sonnenschutztyp: Movable
Fensteröffnung | H2 Ebene +1 | 1155Fen2005804331 | m³ | 0 | Fensterarbeiten | Fensteröffnung | 0 | 3.75 |  | 1155Wa 0000005290 | 0 | - | 0,51 | AllplanAttributes - U-Wert: 0.9; Schallschutzklasse: 32; Sonnenschutztyp: Movable
Fensteröffnung | H2 Ebene +1 | 1155Fen2005804019 | m³ | 0 | Fensterarbeiten | Fensteröffnung | 0 | 3.75 |  | 1155Wa 0000005290 | 0 | - | 0,51 | AllplanAttributes - U-Wert: 0.9; Schallschutzklasse: 32; Sonnenschutztyp: Movable
Fensteröffnung | H2 Ebene +1 | 1155Fen2005804123 | m³ | 0 | Fensterarbeiten | Fensteröffnung | 0 | 3.75 |  | 1155Wa 0000005290 | 0 | - | 0,51 | AllplanAttributes - U-Wert: 0.9; Schallschutzklasse: 32; Sonnenschutztyp: Movable
Fensteröffnung | H2 Ebene +1 | 1155Fen2005804227 | m³ | 0 | Fensterarbeiten | Fensteröffnung | 0 | 3.75 |  | 1155Wa 0000005290 | 0 | - | 0,51 | AllplanAttributes - U-Wert: 0.9; Schallschutzklasse: 32; Sonnenschutztyp: Movable
Fensteröffnung | H2 Ebene +1 | 1155Fen2005804330 | m³ | 0 | Fensterarbeiten | Fensteröffnung | 0 | 3.75 |  | 1155Wa 0000005280 | 0 | - | 0,51 | AllplanAttributes - U-Wert: 0.9; Schallschutzklasse: 32; Sonnenschutztyp: Movable
Fensteröffnung | H2 Ebene +1 | 1155Fen2005804018 | m³ | 0 | Fensterarbeiten | Fensteröffnung | 0 | 3.75 |  | 1155Wa 0000005280 | 0 | - | 0,51 | AllplanAttributes - U-Wert: 0.9; Schallschutzklasse: 32; Sonnenschutztyp: Movable
Fensteröffnung | H2 Ebene +1 | 1155Fen2005804122 | m³ | 0 | Fensterarbeiten | Fensteröffnung | 0 | 3.75 |  | 1155Wa 0000005280 | 0 | - | 0,51 | AllplanAttributes - U-Wert: 0.9; Schallschutzklasse: 32; Sonnenschutztyp: Movable
Fensteröffnung | H2 Ebene +1 | 1155Fen2005804226 | m³ | 0 | Fensterarbeiten | Fensteröffnung | 0 | 3.75 |  | 1155Wa 0000005280 | 0 | - | 0,51 | AllplanAttributes - U-Wert: 0.9; Schallschutzklasse: 32; Sonnenschutztyp: Movable
Fensteröffnung | H2 Ebene +1 | 1155Fen2005804329 | m² | 0 | Fensterarbeiten | Fensteröffnung | 0 | 3.75 |  | 1155Wa 0000005270 | 0 | - | 0,51 | AllplanAttributes - U-Wert: 0.9; Schallschutzklasse: 32; Sonnenschutztyp: Movable
Fensteröffnung | H2 Ebene +1 | 1155Fen2005804017 | m² | 0 | Fensterarbeiten | Fensteröffnung | 0 | 3.75 |  | 1155Wa 0000005270 | 0 | - | 0,51 | AllplanAttributes - U-Wert: 0.9; Schallschutzklasse: 32; Sonnenschutztyp: Movable
Fensteröffnung | H2 Ebene +1 | 1155Fen2005804121 | m² | 0 | Fensterarbeiten | Fensteröffnung | 0 | 3.75 |  | 1155Wa 0000005270 | 0 | - | 0,51 | AllplanAttributes - U-Wert: 0.9; Schallschutzklasse: 32; Sonnenschutztyp: Movable
Fensteröffnung | H2 Ebene +1 | 1155Fen2005804225 | m² | 0 | Fensterarbeiten | Fensteröffnung | 0 | 3.75 |  | 1155Wa 0000005270 | 0 | - | 0,51 | AllplanAttributes - U-Wert: 0.9; Schallschutzklasse: 32; Sonnenschutztyp: Movable
Fensteröffnung | H2 Ebene +1 | 1155Fen2005804328 | m² | 0 | Fensterarbeiten | Fensteröffnung | 0 | 3.75 | NEW | 1155Wa 0000005260 | 0 | - | 0,51 | AllplanAttributes - U-Wert: 0.9; Schallschutzklasse: 32; Sonnenschutztyp: Movable
Fensteröffnung | H2 Ebene +1 | 1155Fen2005804016 | m² | 0 | Fensterarbeiten | Fensteröffnung | 0 | 3.75 | NEW | 1155Wa 0000005260 | 0 | - | 0,51 | AllplanAttributes - U-Wert: 0.9; Schallschutzklasse: 32; Sonnenschutztyp: Movable
Fensteröffnung | H2 Ebene +1 | 1155Fen2005804120 | m² | 0 | Fensterarbeiten | Fensteröffnung | 0 | 3.75 | NEW | 1155Wa 0000005260 | 0 | - | 0,51 | AllplanAttributes - U-Wert: 0.9; Schallschutzklasse: 32; Sonnenschutztyp: Movable
Fensteröffnung | H2 Ebene +1 | 1155Fen2005804224 | m² | 0 | Fensterarbeiten | Fensteröffnung | 0 | 3.75 | NEW | 1155Wa 0000005260 | 0 | - | 0,51 | AllplanAttributes - U-Wert: 0.9; Schallschutzklasse: 32; Sonnenschutztyp: Movable
Fensteröffnung | H2 Ebene +1 | 1155Fen2005804327 | m² | 0 | Fensterarbeiten | Fensteröffnung | 0 | 3.75 | NEW | 1155Wa 0000005250 | 0 | - | 0,51 | AllplanAttributes - U-Wert: 0.9; Schallschutzklasse: 32; Sonnenschutztyp: Movable
Fensteröffnung | H2 Ebene +1 | 1155Fen2005804015 | m² | 0 | Fensterarbeiten | Fensteröffnung | 0 | 3.75 | NEW | 1155Wa 0000005250 | 0 | - | 0,51 | AllplanAttributes - U-Wert: 0.9; Schallschutzklasse: 32; Sonnenschutztyp: Movable
Fensteröffnung | H2 Ebene +1 | 1155Fen2005804119 | m² | 0 | Fensterarbeiten | Fensteröffnung | 0 | 3.75 | NEW | 1155Wa 0000005250 | 0 | - | 0,51 | AllplanAttributes - U-Wert: 0.9; Schallschutzklasse: 32; Sonnenschutztyp: Movable
Fensteröffnung | H2 Ebene +1 | 1155Fen2005804223 | m² | 0 | Fensterarbeiten | Fensteröffnung | 0 | 3.75 | NEW | 1155Wa 0000005250 | 0 | - | 0,51 | AllplanAttributes - U-Wert: 0.9; Schallschutzklasse: 32; Sonnenschutztyp: Movable
Fensteröffnung | H2 Ebene +1 | 1155Fen2005804326 | m² | 0 | Fensterarbeiten | Fensteröffnung | 0 | 3.75 | NEW | 1155Wa 0000005240 | 0 | - | 0,51 | AllplanAttributes - U-Wert: 0.9; Schallschutzklasse: 32; Sonnenschutztyp: Movable
Fensteröffnung | H2 Ebene +1 | 1155Fen2005804014 | m² | 0 | Fensterarbeiten | Fensteröffnung | 0 | 3.75 | NEW | 1155Wa 0000005240 | 0 | - | 0,51 | AllplanAttributes - U-Wert: 0.9; Schallschutzklasse: 32; Sonnenschutztyp: Movable
Fensteröffnung | H2 Ebene +1 | 1155Fen2005804118 | m² | 0 | Fensterarbeiten | Fensteröffnung | 0 | 3.75 | NEW | 1155Wa 0000005240 | 0 | - | 0,51 | AllplanAttributes - U-Wert: 0.9; Schallschutzklasse: 32; Sonnenschutztyp: Movable
Fensteröffnung | H2 Ebene +1 | 1155Fen2005804222 | m² | 0 | Fensterarbeiten | Fensteröffnung | 0 | 3.75 | NEW | 1155Wa 0000005240 | 0 | - | 0,51 | AllplanAttributes - U-Wert: 0.9; Schallschutzklasse: 32; Sonnenschutztyp: Movable
Fensteröffnung | H2 Ebene +1 | 1155Fen2005813669 | m² |  | Wärmedämm-Verbundsysteme | Fensteröffnung |  | 3.75 | NEW | 1155Wa 0000002807 | 0 | - | 0,51 | AllplanAttributes - Material: Fensterelement; Tragendes Bauteil: no; Brandabschnittsdefinierendes Bauteil: no; U-Wert: 0.9; Schallschutzklasse: 32; Sonnenschutztyp: Movable
Fensteröffnung | H2 Ebene +1 | 1155Fen2005813602 | m² |  | Wärmedämm-Verbundsysteme | Fensteröffnung |  | 3.75 | NEW | 1155Wa 0000002807 | 0 | - | 0,51 | AllplanAttributes - Material: Fensterelement; Tragendes Bauteil: no; Brandabschnittsdefinierendes Bauteil: no; U-Wert: 0.9; Schallschutzklasse: 32; Sonnenschutztyp: Movable
Fensteröffnung | H2 Ebene +1 | 1155Fen2005813674 | m³ | 0 | Wärmedämm-Verbundsysteme | Fensteröffnung | 0 | 3.75 | NEW | 1155Wa 0000002803 | 0 | - | 0,51 | AllplanAttributes - Material: Fensterelement; Außenliegend: yes; U-Wert: 0.9; Schallschutzklasse: 32; Sonnenschutztyp: Movable
Fensteröffnung | H2 Ebene +1 | 1155Fen2005813596 | m³ | 0 | Wärmedämm-Verbundsysteme | Fensteröffnung | 0 | 3.75 | NEW | 1155Wa 0000002803 | 0 | - | 0,51 | AllplanAttributes - Material: Fensterelement; Außenliegend: yes; U-Wert: 0.9; Schallschutzklasse: 32; Sonnenschutztyp: Movable
Fensteröffnung | H2 Ebene +1 | 1155Fen2005813671 | m³ | 0 | Wärmedämm-Verbundsysteme | Fensteröffnung | 0 | 3.75 | NEW | 1155Wa 0000002799 | 0 | - | 0,51 | AllplanAttributes - U-Wert: 0.9; Schallschutzklasse: 32; Sonnenschutztyp: Movable
Fensteröffnung | H2 Ebene +1 | 1155Fen2005813599 | m³ | 0 | Wärmedämm-Verbundsysteme | Fensteröffnung | 0 | 3.75 | NEW | 1155Wa 0000002799 | 0 | - | 0,51 | AllplanAttributes - U-Wert: 0.9; Schallschutzklasse: 32; Sonnenschutztyp: Movable
Fensteröffnung | H2 Ebene +1 | 1155Fen2005813672 | m² | 0 | Wärmedämm-Verbundsysteme | Fensteröffnung | 0 | 3.75 | NEW | 1155Wa 0000002795 | 0 | - | 0,51 | AllplanAttributes - U-Wert: 0.9; Schallschutzklasse: 32; Sonnenschutztyp: Movable
Fensteröffnung | H2 Ebene +1 | 1155Fen2005813598 | m² | 0 | Wärmedämm-Verbundsysteme | Fensteröffnung | 0 | 3.75 | NEW | 1155Wa 0000002795 | 0 | - | 0,51 | AllplanAttributes - U-Wert: 0.9; Schallschutzklasse: 32; Sonnenschutztyp: Movable
Fensteröffnung | H2 Ebene +1 | 1155Fen2005813673 | m² | 0 | Wärmedämm-Verbundsysteme | Fensteröffnung | 0 | 3.75 | NEW | 1155Wa 0000002791 | 0 | - | 0,51 | AllplanAttributes - U-Wert: 0.9; Schallschutzklasse: 32; Sonnenschutztyp: Movable
Fensteröffnung | H2 Ebene +1 | 1155Fen2005813597 | m² | 0 | Wärmedämm-Verbundsysteme | Fensteröffnung | 0 | 3.75 | NEW | 1155Wa 0000002791 | 0 | - | 0,51 | AllplanAttributes - U-Wert: 0.9; Schallschutzklasse: 32; Sonnenschutztyp: Movable
Fensteröffnung | H2 Ebene +1 | 1155Fen2005813676 | m² | 0 | Wärmedämm-Verbundsysteme | Fensteröffnung | 0 | 3.75 | NEW | 1155Wa 0000002787 | 0 | - | 0,51 | AllplanAttributes - U-Wert: 0.9; Schallschutzklasse: 32; Sonnenschutztyp: Movable
Fensteröffnung | H2 Ebene +1 | 1155Fen2005813601 | m² | 0 | Wärmedämm-Verbundsysteme | Fensteröffnung | 0 | 3.75 | NEW | 1155Wa 0000002787 | 0 | - | 0,51 | AllplanAttributes - U-Wert: 0.9; Schallschutzklasse: 32; Sonnenschutztyp: Movable
Fensteröffnung | H2 Ebene +1 | 1155Fen2005813675 | m² | 0 | Wärmedämm-Verbundsysteme | Fensteröffnung | 0 | 3.75 | NEW | 1155Wa 0000002783 | 0 | - | 0,51 | AllplanAttributes - U-Wert: 0.9; Schallschutzklasse: 32; Sonnenschutztyp: Movable
Fensteröffnung | H2 Ebene +1 | 1155Fen2005813600 | m² | 0 | Wärmedämm-Verbundsysteme | Fensteröffnung | 0 | 3.75 | NEW | 1155Wa 0000002783 | 0 | - | 0,51 | AllplanAttributes - U-Wert: 0.9; Schallschutzklasse: 32; Sonnenschutztyp: Movable
Fensteröffnung | H2 Ebene +1 | 1155Fen2005818898 | m² |  | Wärmedämm-Verbundsysteme | Fensteröffnung |  | 3.75 | NEW | 1155Wa 0000002572 | 0 | - | 0,51 | AllplanAttributes - Material: Fensterelement; Tragendes Bauteil: no; Brandabschnittsdefinierendes Bauteil: no; U-Wert: 0.9; Schallschutzklasse: 32; Sonnenschutztyp: Movable
Fensteröffnung | H2 Ebene +1 | 1155Fen2005818881 | m³ | 0 | Wärmedämm-Verbundsysteme | Fensteröffnung | 0 | 3.75 | NEW | 1155Wa 0000002576 | 0 | - | 0,51 | AllplanAttributes - Material: Fensterelement; Außenliegend: yes; U-Wert: 0.9; Schallschutzklasse: 32; Sonnenschutztyp: Movable
Fensteröffnung | H2 Ebene +1 | 1155Fen2005818894 | m³ | 0 | Wärmedämm-Verbundsysteme | Fensteröffnung | 0 | 3.75 | NEW | 1155Wa 0000002580 | 0 | - | 0,51 | AllplanAttributes - U-Wert: 0.9; Schallschutzklasse: 32; Sonnenschutztyp: Movable
Fensteröffnung | H2 Ebene +1 | 1155Fen2005818889 | m² | 0 | Wärmedämm-Verbundsysteme | Fensteröffnung | 0 | 3.75 | NEW | 1155Wa 0000002584 | 0 | - | 0,51 | AllplanAttributes - U-Wert: 0.9; Schallschutzklasse: 32; Sonnenschutztyp: Movable
Fensteröffnung | H2 Ebene +1 | 1155Fen2005818879 | m² | 0 | Wärmedämm-Verbundsysteme | Fensteröffnung | 0 | 3.75 | NEW | 1155Wa 0000002588 | 0 | - | 0,51 | AllplanAttributes - U-Wert: 0.9; Schallschutzklasse: 32; Sonnenschutztyp: Movable
Fensteröffnung | H2 Ebene +1 | 1155Fen2005818892 | m² | 0 | Wärmedämm-Verbundsysteme | Fensteröffnung | 0 | 3.75 | NEW | 1155Wa 0000002592 | 0 | - | 0,51 | AllplanAttributes - U-Wert: 0.9; Schallschutzklasse: 32; Sonnenschutztyp: Movable
Fensteröffnung | H2 Ebene +1 | 1155Fen2005818891 | m² | 0 | Wärmedämm-Verbundsysteme | Fensteröffnung | 0 | 3.75 | NEW | 1155Wa 0000002596 | 0 | - | 0,51 | AllplanAttributes - U-Wert: 0.9; Schallschutzklasse: 32; Sonnenschutztyp: Movable
Fensteröffnung | H2 Ebene +1 | 1155Fen2005818896 | m² |  | Wärmedämm-Verbundsysteme | Fensteröffnung |  | 3.75 | NEW | 1155Wa 0000000962 | 0 | - | 0,51 | AllplanAttributes - Material: Fensterelement; Tragendes Bauteil: no; Brandabschnittsdefinierendes Bauteil: no; U-Wert: 0.9; Schallschutzklasse: 32; Sonnenschutztyp: Movable
Fensteröffnung | H2 Ebene +1 | 1155Fen2005818900 | m² |  | Wärmedämm-Verbundsysteme | Fensteröffnung |  | 3.75 | NEW | 1155Wa 0000000962 | 0 | - | 0,51 | AllplanAttributes - Material: Fensterelement; Tragendes Bauteil: no; Brandabschnittsdefinierendes Bauteil: no; U-Wert: 0.9; Schallschutzklasse: 32; Sonnenschutztyp: Movable
Fensteröffnung | H2 Ebene +1 | 1155Fen2005818886 | m³ | 0 | Wärmedämm-Verbundsysteme | Fensteröffnung | 0 | 3.75 | NEW | 1155Wa 0000000958 | 0 | - | 0,51 | AllplanAttributes - Material: Fensterelement; Außenliegend: yes; U-Wert: 0.9; Schallschutzklasse: 32; Sonnenschutztyp: Movable
Fensteröffnung | H2 Ebene +1 | 1155Fen2005818890 | m³ | 0 | Wärmedämm-Verbundsysteme | Fensteröffnung | 0 | 3.75 | NEW | 1155Wa 0000000958 | 0 | - | 0,51 | AllplanAttributes - Material: Fensterelement; Außenliegend: yes; U-Wert: 0.9; Schallschutzklasse: 32; Sonnenschutztyp: Movable
Fensteröffnung | H2 Ebene +1 | 1155Fen2005818884 | m³ | 0 | Wärmedämm-Verbundsysteme | Fensteröffnung | 0 | 3.75 | NEW | 1155Wa 0000000938 | 0 | - | 0,51 | AllplanAttributes - U-Wert: 0.9; Schallschutzklasse: 32; Sonnenschutztyp: Movable
Fensteröffnung | H2 Ebene +1 | 1155Fen2005818893 | m³ | 0 | Wärmedämm-Verbundsysteme | Fensteröffnung | 0 | 3.75 | NEW | 1155Wa 0000000938 | 0 | - | 0,51 | AllplanAttributes - U-Wert: 0.9; Schallschutzklasse: 32; Sonnenschutztyp: Movable
Fensteröffnung | H2 Ebene +1 | 1155Fen2005818878 | m² | 0 | Wärmedämm-Verbundsysteme | Fensteröffnung | 0 | 3.75 | NEW | 1155Wa 0000000942 | 0 | - | 0,51 | AllplanAttributes - U-Wert: 0.9; Schallschutzklasse: 32; Sonnenschutztyp: Movable
Fensteröffnung | H2 Ebene +1 | 1155Fen2005818887 | m² | 0 | Wärmedämm-Verbundsysteme | Fensteröffnung | 0 | 3.75 | NEW | 1155Wa 0000000942 | 0 | - | 0,51 | AllplanAttributes - U-Wert: 0.9; Schallschutzklasse: 32; Sonnenschutztyp: Movable
Fensteröffnung | H2 Ebene +1 | 1155Fen2005818882 | m² | 0 | Wärmedämm-Verbundsysteme | Fensteröffnung | 0 | 3.75 | NEW | 1155Wa 0000000946 | 0 | - | 0,51 | AllplanAttributes - U-Wert: 0.9; Schallschutzklasse: 32; Sonnenschutztyp: Movable
Fensteröffnung | H2 Ebene +1 | 1155Fen2005818883 | m² | 0 | Wärmedämm-Verbundsysteme | Fensteröffnung | 0 | 3.75 | NEW | 1155Wa 0000000946 | 0 | - | 0,51 | AllplanAttributes - U-Wert: 0.9; Schallschutzklasse: 32; Sonnenschutztyp: Movable
Fensteröffnung | H2 Ebene +1 | 1155Fen2005818885 | m² | 0 | Wärmedämm-Verbundsysteme | Fensteröffnung | 0 | 3.75 | NEW | 1155Wa 0000000950 | 0 | - | 0,51 | AllplanAttributes - U-Wert: 0.9; Schallschutzklasse: 32; Sonnenschutztyp: Movable
Fensteröffnung | H2 Ebene +1 | 1155Fen2005818888 | m² | 0 | Wärmedämm-Verbundsysteme | Fensteröffnung | 0 | 3.75 | NEW | 1155Wa 0000000950 | 0 | - | 0,51 | AllplanAttributes - U-Wert: 0.9; Schallschutzklasse: 32; Sonnenschutztyp: Movable
Fensteröffnung | H2 Ebene +1 | 1155Fen2005818880 | m² | 0 | Wärmedämm-Verbundsysteme | Fensteröffnung | 0 | 3.75 | NEW | 1155Wa 0000000954 | 0 | - | 0,51 | AllplanAttributes - U-Wert: 0.9; Schallschutzklasse: 32; Sonnenschutztyp: Movable
Fensteröffnung | H2 Ebene +1 | 1155Fen2005818895 | m² | 0 | Wärmedämm-Verbundsysteme | Fensteröffnung | 0 | 3.75 | NEW | 1155Wa 0000000954 | 0 | - | 0,51 | AllplanAttributes - U-Wert: 0.9; Schallschutzklasse: 32; Sonnenschutztyp: Movable
Fensteröffnung | H2 Ebene +1 | 1155Fen2005819079 | m² |  | Wärmedämm-Verbundsysteme | Fensteröffnung |  | 3.75 | NEW | 1155Wa 0000000910 | 0 | - | 0,51 | AllplanAttributes - Material: Fensterelement; Tragendes Bauteil: no; Brandabschnittsdefinierendes Bauteil: no; U-Wert: 0.9; Schallschutzklasse: 32; Sonnenschutztyp: Movable
Fensteröffnung | H2 Ebene +1 | 1155Fen2005819081 | m² |  | Wärmedämm-Verbundsysteme | Fensteröffnung |  | 3.75 | NEW | 1155Wa 0000000910 | 0 | - | 0,51 | AllplanAttributes - Material: Fensterelement; Tragendes Bauteil: no; Brandabschnittsdefinierendes Bauteil: no; U-Wert: 0.9; Schallschutzklasse: 32; Sonnenschutztyp: Movable
Fensteröffnung | H2 Ebene +1 | 1155Fen2005819088 | m³ | 0 | Wärmedämm-Verbundsysteme | Fensteröffnung | 0 | 3.75 | NEW | 1155Wa 0000000914 | 0 | - | 0,51 | AllplanAttributes - Material: Fensterelement; Außenliegend: yes; U-Wert: 0.9; Schallschutzklasse: 32; Sonnenschutztyp: Movable
Fensteröffnung | H2 Ebene +1 | 1155Fen2005819093 | m³ | 0 | Wärmedämm-Verbundsysteme | Fensteröffnung | 0 | 3.75 | NEW | 1155Wa 0000000914 | 0 | - | 0,51 | AllplanAttributes - Material: Fensterelement; Außenliegend: yes; U-Wert: 0.9; Schallschutzklasse: 32; Sonnenschutztyp: Movable
Fensteröffnung | H2 Ebene +1 | 1155Fen2005819089 | m³ | 0 | Wärmedämm-Verbundsysteme | Fensteröffnung | 0 | 3.75 | NEW | 1155Wa 0000000934 | 0 | - | 0,51 | AllplanAttributes - U-Wert: 0.9; Schallschutzklasse: 32; Sonnenschutztyp: Movable
Fensteröffnung | H2 Ebene +1 | 1155Fen2005819090 | m³ | 0 | Wärmedämm-Verbundsysteme | Fensteröffnung | 0 | 3.75 | NEW | 1155Wa 0000000934 | 0 | - | 0,51 | AllplanAttributes - U-Wert: 0.9; Schallschutzklasse: 32; Sonnenschutztyp: Movable
Fensteröffnung | H2 Ebene +1 | 1155Fen2005819086 | m² | 0 | Wärmedämm-Verbundsysteme | Fensteröffnung | 0 | 3.75 | NEW | 1155Wa 0000000930 | 0 | - | 0,51 | AllplanAttributes - U-Wert: 0.9; Schallschutzklasse: 32; Sonnenschutztyp: Movable
Fensteröffnung | H2 Ebene +1 | 1155Fen2005819092 | m² | 0 | Wärmedämm-Verbundsysteme | Fensteröffnung | 0 | 3.75 | NEW | 1155Wa 0000000930 | 0 | - | 0,51 | AllplanAttributes - U-Wert: 0.9; Schallschutzklasse: 32; Sonnenschutztyp: Movable
Fensteröffnung | H2 Ebene +1 | 1155Fen2005819085 | m² | 0 | Wärmedämm-Verbundsysteme | Fensteröffnung | 0 | 3.75 | NEW | 1155Wa 0000000926 | 0 | - | 0,51 | AllplanAttributes - U-Wert: 0.9; Schallschutzklasse: 32; Sonnenschutztyp: Movable
Fensteröffnung | H2 Ebene +1 | 1155Fen2005819094 | m² | 0 | Wärmedämm-Verbundsysteme | Fensteröffnung | 0 | 3.75 | NEW | 1155Wa 0000000926 | 0 | - | 0,51 | AllplanAttributes - U-Wert: 0.9; Schallschutzklasse: 32; Sonnenschutztyp: Movable
Fensteröffnung | H2 Ebene +1 | 1155Fen2005819083 | m² | 0 | Wärmedämm-Verbundsysteme | Fensteröffnung | 0 | 3.75 | NEW | 1155Wa 0000000922 | 0 | - | 0,51 | AllplanAttributes - U-Wert: 0.9; Schallschutzklasse: 32; Sonnenschutztyp: Movable
Fensteröffnung | H2 Ebene +1 | 1155Fen2005819084 | m² | 0 | Wärmedämm-Verbundsysteme | Fensteröffnung | 0 | 3.75 | NEW | 1155Wa 0000000922 | 0 | - | 0,51 | AllplanAttributes - U-Wert: 0.9; Schallschutzklasse: 32; Sonnenschutztyp: Movable
Fensteröffnung | H2 Ebene +1 | 1155Fen2005819087 | m² | 0 | Wärmedämm-Verbundsysteme | Fensteröffnung | 0 | 3.75 | NEW | 1155Wa 0000000918 | 0 | - | 0,51 | AllplanAttributes - U-Wert: 0.9; Schallschutzklasse: 32; Sonnenschutztyp: Movable
Fensteröffnung | H2 Ebene +1 | 1155Fen2005819091 | m² | 0 | Wärmedämm-Verbundsysteme | Fensteröffnung | 0 | 3.75 | NEW | 1155Wa 0000000918 | 0 | - | 0,51 | AllplanAttributes - U-Wert: 0.9; Schallschutzklasse: 32; Sonnenschutztyp: Movable
Fensteröffnung | H2 Ebene +1 | 1155Fen2005680078 | m² |  | Metallbau-, Schlosserarbeiten | Fensteröffnung |  |  | NEW
Fensteröffnung | H2 Ebene +1 | 1155Fen2005680077 | m² | 0 | Metallbau-, Schlosserarbeiten | Fensteröffnung | 0 |  | NEW
Fensteröffnung | H2 Ebene +1 | 1155Fen2005680076 | m² | 0 | Metallbau-, Schlosserarbeiten | Fensteröffnung | 0 | 11.25 | NEW
Fensteröffnung | H2 Ebene +1 | 1155Fen2005680066 | m² | 0 | Metallbau-, Schlosserarbeiten | Fensteröffnung | 0 | 11.25 | NEW
Fensteröffnung | H2 Ebene +1 | 1155Fen2005680065 | m² | 0 | Metallbau-, Schlosserarbeiten | Fensteröffnung | 0 | 11.25 | NEW
Fensteröffnung | H2 Ebene +1 | 1155Fen2005680064 | m² | 0 | Metallbau-, Schlosserarbeiten | Fensteröffnung | 0 | 11.25 | NEW
Fensteröffnung | H2 Ebene +1 | 1155Fen2005679225 | m² |  | Metallbau-, Schlosserarbeiten | Fensteröffnung |  |  | NEW
Fensteröffnung | H2 Ebene +1 | 1155Fen2005679226 | m² | 0 | Metallbau-, Schlosserarbeiten | Fensteröffnung | 0 |  | NEW
Fensteröffnung | H2 Ebene +1 | 1155Fen2005679227 | m² | 0 | Metallbau-, Schlosserarbeiten | Fensteröffnung | 0 | 11.25 | NEW
Fensteröffnung | H2 Ebene +1 | 1155Fen2005679228 | m² | 0 | Metallbau-, Schlosserarbeiten | Fensteröffnung | 0 | 11.25 | NEW
Fensteröffnung | H2 Ebene +1 | 1155Fen2005679229 | m² | 0 | Metallbau-, Schlosserarbeiten | Fensteröffnung | 0 | 11.25 | NEW
Fensteröffnung | H2 Ebene +1 | 1155Fen2005679230 | m² | 0 | Metallbau-, Schlosserarbeiten | Fensteröffnung | 0 | 11.25 | NEW
Fensteröffnung | H2 Ebene +1 | 1155Fen0000084913 | m² |  | Fensterarbeiten | Fensteröffnung |  | 3.75 |  | 1155Wa 0000084196 | 0 | - | 0,51 | AllplanAttributes - U-Wert: 0.9; Schallschutzklasse: 32; Sonnenschutztyp: Movable
Fensteröffnung | H2 Ebene +1 | 1155Fen0000084912 | m³ | 0 | Fensterarbeiten | Fensteröffnung | 0 | 3.75 |  | 1155Wa 0000084197 | 0 | - | 0,51 | AllplanAttributes - U-Wert: 0.9; Schallschutzklasse: 32; Sonnenschutztyp: Movable
Fensteröffnung | H2 Ebene +1 | 1155Fen0000084911 | m³ | 0 | Fensterarbeiten | Fensteröffnung | 0 | 3.75 |  | 1155Wa 0000084198 | 0 | - | 0,51 | AllplanAttributes - U-Wert: 0.9; Schallschutzklasse: 32; Sonnenschutztyp: Movable
Fensteröffnung | H2 Ebene +1 | 1155Fen0000084910 | m² | 0 | Fensterarbeiten | Fensteröffnung | 0 | 3.75 |  | 1155Wa 0000084199 | 0 | - | 0,51 | AllplanAttributes - U-Wert: 0.9; Schallschutzklasse: 32; Sonnenschutztyp: Movable
Fensteröffnung | H2 Ebene +1 | 1155Fen0000084909 | m² | 0 | Fensterarbeiten | Fensteröffnung | 0 | 3.75 | NEW | 1155Wa 0000084200 | 0 | - | 0,51 | AllplanAttributes - U-Wert: 0.9; Schallschutzklasse: 32; Sonnenschutztyp: Movable
Fensteröffnung | H2 Ebene +1 | 1155Fen0000084908 | m² | 0 | Fensterarbeiten | Fensteröffnung | 0 | 3.75 | NEW | 1155Wa 0000084201 | 0 | - | 0,51 | AllplanAttributes - U-Wert: 0.9; Schallschutzklasse: 32; Sonnenschutztyp: Movable
Fensteröffnung | H2 Ebene +1 | 1155Fen0000084907 | m² | 0 | Fensterarbeiten | Fensteröffnung | 0 | 3.75 | NEW | 1155Wa 0000084202 | 0 | - | 0,51 | AllplanAttributes - U-Wert: 0.9; Schallschutzklasse: 32; Sonnenschutztyp: Movable
Türöffnung | H2 Ebene +1 | 1163Tür0812440433 | m² |  | Trockenbauarbeiten | Türöffnung |  | 3.75 | NEW | 1163Wa 0812443609 | AllplanAttributes - Bezeichnung: Türöffnung; Codetext: Codetext; Türanschlag: -; Attributset-Objekt: OpeningElement; Positionsnummer_Text: U100; Ortscode_Geschoßbezeichnung: E01; Pset_OpeningElementCommon - FireExit: no; Reference: Codetext
Türöffnung | H2 Ebene +1 | 1163Tür0812436414 | m² |  | Trockenbauarbeiten | Türöffnung |  | 3.75 | NEW | 1163Wa 0812437641 | AllplanAttributes - Bezeichnung: Türöffnung; Codetext: Codetext; Türanschlag: -; Attributset-Objekt: OpeningElement; Positionsnummer_Text: U100; Ortscode_Geschoßbezeichnung: E01; Pset_OpeningElementCommon - FireExit: no; Reference: Codetext
Türöffnung | H2 Ebene +1 | 1163Tür0812549652 | m² |  | Trockenbauarbeiten | Türöffnung |  | 3.75 | NEW | 1163Wa 0812549763 | EI2 30 | AllplanAttributes - Codetext: Codetext; Türanschlag: -; Attributset-Objekt: OpeningElement; Rauchschutz: yes; Selbstschließend: yes; ash T_Zulage Schachttür: no; ash T_Dichtschließend: no; ash T_Feststellanlage (FSA): -; ash T_nicht abschließbar: no; Positionsnummer_Text: U100; Ortscode_Geschoßbezeichnung: E01; Pset_OpeningElementCommon - FireExit: no; Reference: Codetext
Türöffnung | H2 Ebene +1 | 1163Tür0812549649 | m² |  | Trockenbauarbeiten | Türöffnung |  | 3.75 | NEW | 1163Wa 0812549763 | AllplanAttributes - Codetext: Codetext; Türanschlag: -; Attributset-Objekt: OpeningElement; Positionsnummer_Text: U100; Ortscode_Geschoßbezeichnung: E01; Pset_OpeningElementCommon - FireExit: no; Reference: Codetext
Türöffnung | H2 Ebene +1 | 1163Tür0812443590 | m² |  | Trockenbauarbeiten | Türöffnung |  | 3.75 | NEW | 1163Wa 0812443694 | AllplanAttributes - Codetext: Codetext; Türanschlag: DIN R; Attributset-Objekt: OpeningElement; Positionsnummer_Text: U100; Ortscode_Geschoßbezeichnung: E01; Pset_OpeningElementCommon - FireExit: no; Reference: Codetext
Türöffnung | H2 Ebene +1 | 1163Tür0812443594 | m² |  | Trockenbauarbeiten | Türöffnung |  | 3.75 | NEW | 1163Wa 0812443694 | AllplanAttributes - Codetext: Codetext; Türanschlag: DIN L; Attributset-Objekt: OpeningElement; Positionsnummer_Text: U100; Ortscode_Geschoßbezeichnung: E01; Pset_OpeningElementCommon - FireExit: no; Reference: Codetext
SMT | H2 Ebene +1 | 1163Tür0812436302 | m² |  | Zimmer- und Holzbauarbeiten | Türmakro |  | 3.75 | NEW | 1163Wa 0812437646 | AllplanAttributes - Material: TI-1F-UZ-D; Codetext: Codetext; Türanschlag: DIN L; Attributset-Objekt: Door; Glasanteil_berücksichtigen: 100; ash T_Zulage Schachttür: no; ash T_Dichtschließend: no; ash T_Zarge_Typ: U; ash T_Erforderl. Durchgangsbreite: 0 m; ash T_Türblatt sichtbar 2D: ja; ash T_Feststellanlage (FSA): -; ash T_nicht abschließbar: no; ash T_Tür-Nr.: Innentür 1; ash T_Blatt_Oberfläche: -; ash T_Erford. Durgangshöhe: 0 m; ash T_Blatt_Material: -; ash T_Schallschutz: -; ash T_Zarge_Material: S; ash T_Raum zugehörigkeit: BS; Positionsnummer_Text: U100; Ortscode_Geschoßbezeichnung: E01; Pset_OpeningElementCommon - FireExit: no; Reference: Codetext; DoorCommon - Außenliegend: no; Feuerwiderstandsklasse: EI2 30; Rauchschutz: yes; Selbstschließend: yes
Türöffnung | H2 Ebene +1 | 1163Tür0812655403 | m² |  | Trockenbauarbeiten | Türöffnung |  | 3.75 | NEW | 1163Wa 0812655407 | AllplanAttributes - Codetext: Codetext; Türanschlag: DIN R; Attributset-Objekt: OpeningElement; Positionsnummer_Text: U100; Ortscode_Geschoßbezeichnung: E01; Pset_OpeningElementCommon - FireExit: no; Reference: Codetext
Türöffnung | H2 Ebene +1 | 1163Tür0812655401 | m² |  | Trockenbauarbeiten | Türöffnung |  | 3.75 | NEW | 1163Wa 0812655407 | AllplanAttributes - Codetext: Codetext; Türanschlag: DIN L; Attributset-Objekt: OpeningElement; Positionsnummer_Text: U100; Ortscode_Geschoßbezeichnung: E01; Pset_OpeningElementCommon - FireExit: no; Reference: Codetext
Türöffnung | H2 Ebene +1 | 1163Tür0812445989 | m² |  | Trockenbauarbeiten | Türöffnung |  | 3.75 | NEW | 1163Wa 0812446187 | AllplanAttributes - Bezeichnung: Türöffnung; Codetext: Codetext; Türanschlag: -; Attributset-Objekt: OpeningElement; Positionsnummer_Text: U100; Ortscode_Geschoßbezeichnung: E01; Pset_OpeningElementCommon - FireExit: no; Reference: Codetext
Türöffnung | H2 Ebene +1 | 1163Tür0812445981 | m² |  | Trockenbauarbeiten | Türöffnung |  | 3.75 | NEW | 1163Wa 0812446175 | AllplanAttributes - Bezeichnung: Türöffnung; Codetext: Codetext; Türanschlag: -; Attributset-Objekt: OpeningElement; Positionsnummer_Text: U100; Ortscode_Geschoßbezeichnung: E01; Pset_OpeningElementCommon - FireExit: no; Reference: Codetext
Türöffnung | H2 Ebene +1 | 1163Tür0812445977 | m² |  | Trockenbauarbeiten | Türöffnung |  | 3.75 | NEW | 1163Wa 0812446183 | AllplanAttributes - Bezeichnung: Türöffnung; Codetext: Codetext; Türanschlag: -; Attributset-Objekt: OpeningElement; Positionsnummer_Text: U100; Ortscode_Geschoßbezeichnung: E01; Pset_OpeningElementCommon - FireExit: no; Reference: Codetext
Türöffnung | H2 Ebene +1 | 1163Tür0812445973 | m² |  | Trockenbauarbeiten | Türöffnung |  | 3.75 | NEW | 1163Wa 0812446179 | AllplanAttributes - Bezeichnung: Türöffnung; Codetext: Codetext; Türanschlag: -; Attributset-Objekt: OpeningElement; Positionsnummer_Text: U100; Ortscode_Geschoßbezeichnung: E01; Pset_OpeningElementCommon - FireExit: no; Reference: Codetext
Türöffnung | H2 Ebene +1 | 1163Tür0812445969 | m² |  | Trockenbauarbeiten | Türöffnung |  | 3.75 | NEW | 1163Wa 0812446167 | AllplanAttributes - Bezeichnung: Türöffnung; Codetext: Codetext; Türanschlag: -; Attributset-Objekt: OpeningElement; Positionsnummer_Text: U100; Ortscode_Geschoßbezeichnung: E01; Pset_OpeningElementCommon - FireExit: no; Reference: Codetext
Türöffnung | H2 Ebene +1 | 1163Tür0812440139 | m² |  | Trockenbauarbeiten | Türöffnung |  | 3.75 | NEW | 1163Wa 0812440257 | AllplanAttributes - Bezeichnung: Türöffnung; Codetext: Codetext; Türanschlag: -; Attributset-Objekt: OpeningElement; Positionsnummer_Text: U100; Ortscode_Geschoßbezeichnung: E01; Pset_OpeningElementCommon - FireExit: no; Reference: Codetext
Türöffnung | H2 Ebene +1 | 1163Tür0812436847 | m² |  | Trockenbauarbeiten | Türöffnung |  | 3.75 | NEW | 1163Wa 0812438242 | AllplanAttributes - Bezeichnung: Türöffnung; Codetext: Codetext; Türanschlag: -; Attributset-Objekt: OpeningElement; Positionsnummer_Text: U100; Ortscode_Geschoßbezeichnung: E01; Pset_OpeningElementCommon - FireExit: no; Reference: Codetext
Türöffnung | H2 Ebene +1 | 1163Tür0812436843 | m² |  | Trockenbauarbeiten | Türöffnung |  | 3.75 | NEW | 1163Wa 0812438246 | AllplanAttributes - Bezeichnung: Türöffnung; Codetext: Codetext; Türanschlag: -; Attributset-Objekt: OpeningElement; Positionsnummer_Text: U100; Ortscode_Geschoßbezeichnung: E01; Pset_OpeningElementCommon - FireExit: no; Reference: Codetext
Türöffnung | H2 Ebene +1 | 1163Tür0812436838 | m² |  | Trockenbauarbeiten | Türöffnung |  | 3.75 | NEW | 1163Wa 0812438254 | AllplanAttributes - Bezeichnung: Türöffnung; Codetext: Codetext; Türanschlag: -; Attributset-Objekt: OpeningElement; Positionsnummer_Text: U100; Ortscode_Geschoßbezeichnung: E01; Pset_OpeningElementCommon - FireExit: no; Reference: Codetext
Türöffnung | H2 Ebene +1 | 1163Tür0812436855 | m² |  | Trockenbauarbeiten | Türöffnung |  | 3.75 | NEW | 1163Wa 0812438258 | AllplanAttributes - Bezeichnung: Türöffnung; Codetext: Codetext; Türanschlag: -; Attributset-Objekt: OpeningElement; Positionsnummer_Text: U100; Ortscode_Geschoßbezeichnung: E01; Pset_OpeningElementCommon - FireExit: no; Reference: Codetext
Türöffnung | H2 Ebene +1 | 1163Tür0812436851 | m² |  | Trockenbauarbeiten | Türöffnung |  | 3.75 | NEW | 1163Wa 0812438238 | AllplanAttributes - Bezeichnung: Türöffnung; Codetext: Codetext; Türanschlag: -; Attributset-Objekt: OpeningElement; Positionsnummer_Text: U100; Ortscode_Geschoßbezeichnung: E01; Pset_OpeningElementCommon - FireExit: no; Reference: Codetext
Türöffnung | H2 Ebene +1 | 1163Tür0812436859 | m² |  | Trockenbauarbeiten | Türöffnung |  | 3.75 | NEW | 1163Wa 0812438250 | AllplanAttributes - Bezeichnung: Türöffnung; Codetext: Codetext; Türanschlag: -; Attributset-Objekt: OpeningElement; Positionsnummer_Text: U100; Ortscode_Geschoßbezeichnung: E01; Pset_OpeningElementCommon - FireExit: no; Reference: Codetext
Türöffnung | H2 Ebene +1 | 1163Tür0812549299 | m² |  | Trockenbauarbeiten | Türöffnung |  | 3.75 | NEW | 1163Wa 0812549302 | EI2 30 | AllplanAttributes - Codetext: Codetext; Türanschlag: -; Attributset-Objekt: OpeningElement; Rauchschutz: yes; Selbstschließend: yes; ash T_Zulage Schachttür: no; ash T_Dichtschließend: no; ash T_Feststellanlage (FSA): -; ash T_nicht abschließbar: no; Positionsnummer_Text: U100; Ortscode_Geschoßbezeichnung: E01; Pset_OpeningElementCommon - FireExit: no; Reference: Codetext
SMT | H2 Ebene +1 | 1163Tür0812551382 | m² |  | Metallbau-, Schlosserarbeiten | Türmakro |  | 3.75 | NEW | 1163Wa 0812551359 | AllplanAttributes - Material: TI-1F-UZ-D; Codetext: Codetext; Türanschlag: DIN R; Attributset-Objekt: Door; Positionsnummer: 1; V6: 0 m; V7: 0 m; V8: 0 m; V9: 0; Glasanteil_berücksichtigen: 100; ash T_Unterschnitt: -; ash T_Zulage Schachttür: no; ash T_Dichtschließend: yes; ash T_Zarge_Typ: U; ash T_Erforderl. Durchgangsbreite: 0 m; ash T_Türblatt sichtbar 2D: ja; ash T_Feststellanlage (FSA): -; ash T_nicht abschließbar: no; ash T_Blatt_Oberfläche: -; ash T_Erford. Durgangshöhe: 0 m; ash T_Blatt_Material: -; ash T_Schallschutz: -; ash T_Zarge_Material: S; ash T_Raum zugehörigkeit: BS; Positionsnummer_Text: U100; Ortscode_Geschoßbezeichnung: E01; Pset_OpeningElementCommon - FireExit: no; Reference: Codetext; DoorCommon - Außenliegend: no; Feuerwiderstandsklasse: -; Rauchschutz: no; Selbstschließend: no
Türöffnung | H2 Ebene +1 | 1163Tür0812445985 | m² |  | Trockenbauarbeiten | Türöffnung |  | 3.75 | NEW | 1163Wa 0812446171 | AllplanAttributes - Bezeichnung: Türöffnung; Codetext: Codetext; Türanschlag: -; Attributset-Objekt: OpeningElement; Positionsnummer_Text: U100; Ortscode_Geschoßbezeichnung: E01; Pset_OpeningElementCommon - FireExit: no; Reference: Codetext
Türöffnung | H2 Ebene +1 | 1163Tür0812742291 | m² |  | Trockenbauarbeiten | Türöffnung |  | 3.75 | NEW | 1163Wa 0812742684 | EI2 30 | AllplanAttributes - Codetext: Codetext; Türanschlag: -; Attributset-Objekt: OpeningElement; Rauchschutz: yes; Selbstschließend: yes; ash T_Zulage Schachttür: no; ash T_Dichtschließend: no; ash T_Feststellanlage (FSA): -; ash T_nicht abschließbar: no; Positionsnummer_Text: U100; Ortscode_Geschoßbezeichnung: E01; Pset_OpeningElementCommon - FireExit: no; Reference: Codetext
Türöffnung | H2 Ebene +1 | 1163Tür0812742290 | m² |  | Trockenbauarbeiten | Türöffnung |  | 3.75 | NEW | 1163Wa 0812742684 | EI2 30 | AllplanAttributes - Codetext: Codetext; Türanschlag: -; Attributset-Objekt: OpeningElement; Rauchschutz: yes; Selbstschließend: yes; ash T_Zulage Schachttür: no; ash T_Dichtschließend: no; ash T_Feststellanlage (FSA): -; ash T_nicht abschließbar: no; Positionsnummer_Text: U100; Ortscode_Geschoßbezeichnung: E01; Pset_OpeningElementCommon - FireExit: no; Reference: Codetext
Türöffnung | H2 Ebene +1 | 1163Tür0813714679 | m² |  | Trockenbauarbeiten | Türöffnung |  | 3.75 | NEW | 1163Wa 0813714683 | AllplanAttributes - Codetext: Codetext; Türanschlag: -; Attributset-Objekt: OpeningElement; Positionsnummer_Text: U100; Pset_OpeningElementCommon - FireExit: no; Reference: Codetext
Türöffnung | H2 Ebene +1 | 1163Tür0814182431 | m² |  | Zimmer- und Holzbauarbeiten | Türöffnung |  | 3.75 | NEW | 1163Wa 0812492978 | AllplanAttributes - Codetext: Codetext; Türanschlag: DIN L; Attributset-Objekt: OpeningElement; Positionsnummer_Text: U100; Pset_OpeningElementCommon - FireExit: no; Reference: Codetext
Türöffnung | H2 Ebene +1 | 1163Tür0814182423 | m² | 0 | Zimmer- und Holzbauarbeiten | Türöffnung | 0 |  | NEW | 1163Wa 0813789687 | AllplanAttributes - Türanschlag: DIN L; Positionsnummer_Text: U100
Türöffnung | H2 Ebene +1 | 1163Tür0814182421 | m² | 0 | Zimmer- und Holzbauarbeiten | Türöffnung | 0 |  | NEW | 1163Wa 0813789688 | AllplanAttributes - Türanschlag: DIN L; Positionsnummer_Text: U100
SMT | H2 Ebene +1 | 1163Tür0812440816 | m² |  | Zimmer- und Holzbauarbeiten | Türmakro |  | 3.75 | NEW | 1163Wa 0812443013 | AllplanAttributes - Material: TI-1F-UZ-D; Codetext: Codetext; Türanschlag: DIN R; Attributset-Objekt: Door; Glasanteil_berücksichtigen: 100; ash T_Zulage Schachttür: no; ash T_Dichtschließend: no; ash T_Zarge_Typ: U; ash T_Erforderl. Durchgangsbreite: 0 m; ash T_Türblatt sichtbar 2D: ja; ash T_Feststellanlage (FSA): -; ash T_nicht abschließbar: no; ash T_Tür-Nr.: Innentür 1; ash T_Blatt_Oberfläche: -; ash T_Erford. Durgangshöhe: 0 m; ash T_Blatt_Material: -; ash T_Schallschutz: -; ash T_Zarge_Material: S; ash T_Raum zugehörigkeit: BS; Positionsnummer_Text: U100; Ortscode_Geschoßbezeichnung: E01; Pset_OpeningElementCommon - FireExit: no; Reference: Codetext; DoorCommon - Außenliegend: no; Feuerwiderstandsklasse: EI2 30; Rauchschutz: yes; Selbstschließend: yes
Wandnische | H2 Ebene +1 | 1163Wni0814491498 | m² | 0 | Zimmer- und Holzbauarbeiten | Wandnische | 0 |  | NEW
Türöffnung | H2 Ebene +1 | 1163Tür0812852030 | m² |  | Zimmer- und Holzbauarbeiten | Türöffnung |  | 3.75 | NEW | 1163Wa 0812852060 | E 60 | AllplanAttributes - Türanschlag: -; Text1: 15a; Positionsnummer_Text: U100
Türöffnung | H2 Ebene +1 | 1163Tür0813697686 | m² |  | Zimmer- und Holzbauarbeiten | Türöffnung |  | 3.75 | NEW | 1163Wa 0812852060 | E 60 | AllplanAttributes - Türanschlag: -; Text1: 15a; Positionsnummer_Text: U100
Türöffnung | H2 Ebene +1 | 1163Tür0812523044 | m² |  | Zimmer- und Holzbauarbeiten | Türöffnung |  | 3.75 | NEW | 1163Wa 0812444104 | AllplanAttributes - Codetext: Codetext; Türanschlag: DIN R; Attributset-Objekt: OpeningElement; Positionsnummer_Text: U100; Pset_OpeningElementCommon - FireExit: no; Reference: Codetext
Türöffnung | H2 Ebene +1 | 1163Tür0813781680 | m² | 0 | Zimmer- und Holzbauarbeiten | Türöffnung | 0 |  | NEW | 1163Wa 0813781658 | AllplanAttributes - Türanschlag: DIN R; Positionsnummer_Text: U100
Türöffnung | H2 Ebene +1 | 1163Tür0812774560 | m² |  | Zimmer- und Holzbauarbeiten | Türöffnung |  | 3.75 | NEW | 1163Wa 0812774550 | AllplanAttributes - Codetext: Codetext; Türanschlag: DIN R; Attributset-Objekt: OpeningElement; Positionsnummer_Text: U100; Pset_OpeningElementCommon - FireExit: no; Reference: Codetext
Türöffnung | H2 Ebene +1 | 1163Tür0813787004 | m² | 0 | Zimmer- und Holzbauarbeiten | Türöffnung | 0 |  | NEW | 1163Wa 0813786979 | AllplanAttributes - Türanschlag: DIN R; Positionsnummer_Text: U100
Türöffnung | H2 Ebene +1 | 1163Tür0813787202 | m² | 0 | Zimmer- und Holzbauarbeiten | Türöffnung | 0 |  | NEW | 1163Wa 0813787154 | AllplanAttributes - Türanschlag: DIN R; Positionsnummer_Text: U100
Türöffnung | H2 Ebene +1 | 1163Tür0812446813 | m² |  | Zimmer- und Holzbauarbeiten | Türöffnung |  | 3.75 | NEW | 1163Wa 0812446823 | AllplanAttributes - Codetext: Codetext; Türanschlag: DIN L; Attributset-Objekt: OpeningElement; Positionsnummer_Text: U100; Pset_OpeningElementCommon - FireExit: no; Reference: Codetext
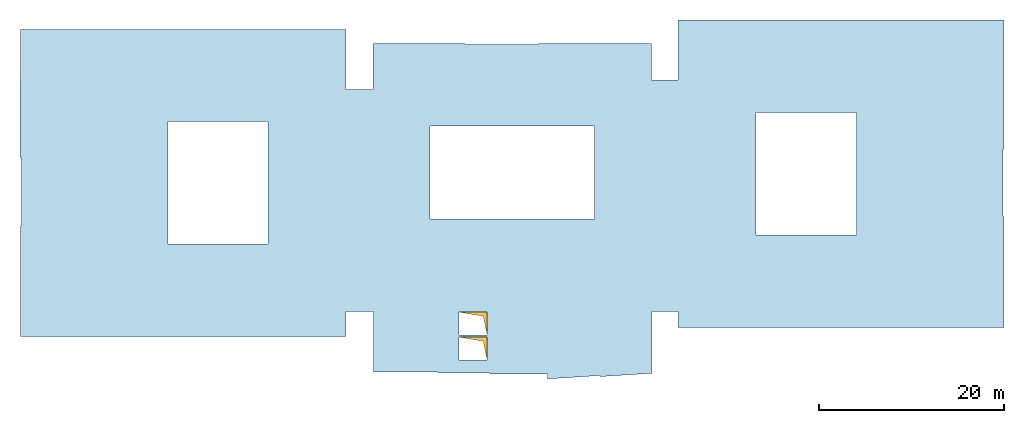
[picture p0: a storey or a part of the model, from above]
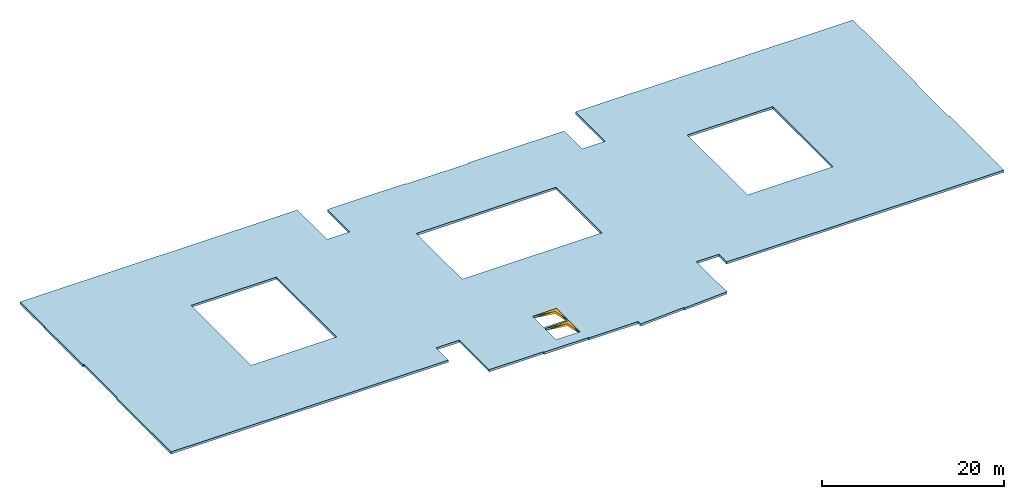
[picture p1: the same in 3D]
Properties of the parts of a building model (IFC4), part 38 of 80

# IfcOpeningElement: Opening (3497)
Name | In | Allright_Bauteil_ID | Abrechnungsart | Versatz_oben | Gewerk | Objektname | Versatz_unten | OKFF | Status | P_ID | AllplanAttributes, Feuerwiderstandsklasse | Sicherheitsklasse | g-Wert
Türöffnung | H2 Ebene +1 | 1163Tür0813784273 | m² | 0 | Zimmer- und Holzbauarbeiten | Türöffnung | 0 |  | NEW | 1163Wa 0813784241 | AllplanAttributes - Türanschlag: DIN L; Positionsnummer_Text: U100
Türöffnung | H2 Ebene +1 | 1163Tür0813784463 | m² | 0 | Zimmer- und Holzbauarbeiten | Türöffnung | 0 |  | NEW | 1163Wa 0813784428 | AllplanAttributes - Türanschlag: DIN L; Positionsnummer_Text: U100
Türöffnung | H2 Ebene +1 | 1163Tür0812543259 | m² |  | Zimmer- und Holzbauarbeiten | Türöffnung |  | 3.75 | NEW | 1163Wa 0812543262 | AllplanAttributes - Codetext: Codetext; Türanschlag: DIN L; Attributset-Objekt: OpeningElement; Positionsnummer_Text: U100; Pset_OpeningElementCommon - FireExit: no; Reference: Codetext
Türöffnung | H2 Ebene +1 | 1163Tür0813786086 | m² | 0 | Zimmer- und Holzbauarbeiten | Türöffnung | 0 |  | NEW | 1163Wa 0813786056 | AllplanAttributes - Türanschlag: DIN L; Positionsnummer_Text: U100
Türöffnung | H2 Ebene +1 | 1163Tür0813786087 | m² | 0 | Zimmer- und Holzbauarbeiten | Türöffnung | 0 |  | NEW | 1163Wa 0813786057 | AllplanAttributes - Türanschlag: DIN L; Positionsnummer_Text: U100
Türöffnung | H2 Ebene +1 | 1163Tür0812438158 | m² |  | Zimmer- und Holzbauarbeiten | Türöffnung |  | 3.75 | NEW | 1163Wa 0812447441 | AllplanAttributes - Codetext: Codetext; Türanschlag: DIN R; Attributset-Objekt: OpeningElement; Positionsnummer_Text: U100; Pset_OpeningElementCommon - FireExit: no; Reference: Codetext
Türöffnung | H2 Ebene +1 | 1163Tür0813786503 | m² | 0 | Zimmer- und Holzbauarbeiten | Türöffnung | 0 |  | NEW | 1163Wa 0813786483 | AllplanAttributes - Türanschlag: DIN R; Positionsnummer_Text: U100
Türöffnung | H2 Ebene +1 | 1163Tür0813786504 | m² | 0 | Zimmer- und Holzbauarbeiten | Türöffnung | 0 |  | NEW | 1163Wa 0813786484 | AllplanAttributes - Türanschlag: DIN R; Positionsnummer_Text: U100
Türöffnung | H2 Ebene +1 | 1163Tür0812435729 | m² |  | Zimmer- und Holzbauarbeiten | Türöffnung |  | 3.75 | NEW | 1163Wa 0812447147 | AllplanAttributes - Codetext: Codetext; Türanschlag: DIN L; Attributset-Objekt: OpeningElement; Positionsnummer_Text: U100; Pset_OpeningElementCommon - FireExit: no; Reference: Codetext
Türöffnung | H2 Ebene +1 | 1163Tür0813783639 | m² | 0 | Zimmer- und Holzbauarbeiten | Türöffnung | 0 |  | NEW | 1163Wa 0813783619 | AllplanAttributes - Türanschlag: DIN L; Positionsnummer_Text: U100
Türöffnung | H2 Ebene +1 | 1163Tür0813783640 | m² | 0 | Zimmer- und Holzbauarbeiten | Türöffnung | 0 |  | NEW | 1163Wa 0813783620 | AllplanAttributes - Türanschlag: DIN L; Positionsnummer_Text: U100
Türöffnung | H2 Ebene +1 | 1163Tür0814183044 | m² |  | Zimmer- und Holzbauarbeiten | Türöffnung |  | 3.75 | NEW | 1163Wa 0812492978 | AllplanAttributes - Codetext: Codetext; Türanschlag: DIN R; Attributset-Objekt: OpeningElement; Positionsnummer_Text: U100; Pset_OpeningElementCommon - FireExit: no; Reference: Codetext
Türöffnung | H2 Ebene +1 | 1163Tür0814183054 | m² | 0 | Zimmer- und Holzbauarbeiten | Türöffnung | 0 |  | NEW | 1163Wa 0813789687 | AllplanAttributes - Türanschlag: DIN R; Positionsnummer_Text: U100
Türöffnung | H2 Ebene +1 | 1163Tür0814183057 | m² | 0 | Zimmer- und Holzbauarbeiten | Türöffnung | 0 |  | NEW | 1163Wa 0813789688 | AllplanAttributes - Türanschlag: DIN R; Positionsnummer_Text: U100
Türöffnung | H2 Ebene +1 | 1163Tür0812492974 | m² |  | Zimmer- und Holzbauarbeiten | Türöffnung |  | 3.75 | NEW | 1163Wa 0812492978 | AllplanAttributes - Codetext: Codetext; Türanschlag: DIN L; Attributset-Objekt: OpeningElement; Positionsnummer_Text: U100; Pset_OpeningElementCommon - FireExit: no; Reference: Codetext
Türöffnung | H2 Ebene +1 | 1163Tür0813789710 | m² | 0 | Zimmer- und Holzbauarbeiten | Türöffnung | 0 |  | NEW | 1163Wa 0813789687 | AllplanAttributes - Türanschlag: DIN L; Positionsnummer_Text: U100
Türöffnung | H2 Ebene +1 | 1163Tür0813789711 | m² | 0 | Zimmer- und Holzbauarbeiten | Türöffnung | 0 |  | NEW | 1163Wa 0813789688 | AllplanAttributes - Türanschlag: DIN L; Positionsnummer_Text: U100
Türöffnung | H2 Ebene +1 | 1163Tür0814179150 | m² |  | Zimmer- und Holzbauarbeiten | Türöffnung |  | 3.75 | NEW | 1163Wa 0812492978 | AllplanAttributes - Codetext: Codetext; Türanschlag: DIN L; Attributset-Objekt: OpeningElement; Positionsnummer_Text: U100; Pset_OpeningElementCommon - FireExit: no; Reference: Codetext
Türöffnung | H2 Ebene +1 | 1163Tür0814179162 | m² | 0 | Zimmer- und Holzbauarbeiten | Türöffnung | 0 |  | NEW | 1163Wa 0813789687 | AllplanAttributes - Türanschlag: DIN L; Positionsnummer_Text: U100
Türöffnung | H2 Ebene +1 | 1163Tür0814179158 | m² | 0 | Zimmer- und Holzbauarbeiten | Türöffnung | 0 |  | NEW | 1163Wa 0813789688 | AllplanAttributes - Türanschlag: DIN L; Positionsnummer_Text: U100
Türöffnung | H2 Ebene +1 | 1163Tür0812435698 | m² |  | Zimmer- und Holzbauarbeiten | Türöffnung |  | 3.75 | NEW | 1163Wa 0812447076 | AllplanAttributes - Codetext: Codetext; Türanschlag: DIN R; Attributset-Objekt: OpeningElement; Positionsnummer_Text: U100; Pset_OpeningElementCommon - FireExit: no; Reference: Codetext
Türöffnung | H2 Ebene +1 | 1163Tür0813784825 | m² | 0 | Zimmer- und Holzbauarbeiten | Türöffnung | 0 |  | NEW | 1163Wa 0813784806 | AllplanAttributes - Türanschlag: -; Positionsnummer_Text: U100
Türöffnung | H2 Ebene +1 | 1163Tür0812535682 | m² |  | Trockenbauarbeiten | Türöffnung |  | 3.75 | NEW | 1163Wa 0812447085 | AllplanAttributes - Codetext: Codetext; Türanschlag: -; Attributset-Objekt: OpeningElement; Positionsnummer_Text: U100; Pset_OpeningElementCommon - FireExit: no; Reference: Codetext
Türöffnung | H2 Ebene +1 | 1163Tür0812435696 | m² |  | Zimmer- und Holzbauarbeiten | Türöffnung |  | 3.75 | NEW | 1163Wa 0812447102 | AllplanAttributes - Codetext: Codetext; Türanschlag: DIN L; Attributset-Objekt: OpeningElement; Positionsnummer_Text: U100; Pset_OpeningElementCommon - FireExit: no; Reference: Codetext
Türöffnung | H2 Ebene +1 | 1163Tür0813785759 | m² | 0 | Zimmer- und Holzbauarbeiten | Türöffnung | 0 |  | NEW | 1163Wa 0813785740 | AllplanAttributes - Türanschlag: -; Positionsnummer_Text: U100
Fensteröffnung | H2 Ebene +1 | 1163Fen0814462041 | m² |  | Fensterarbeiten | Fensteröffnung |  | 0 |  | 1113Wa 0812437264 | AllplanAttributes - ash D_Detailverweis: D1833; Positionsnummer_Text: S68
Türöffnung | H2 Ebene +1 | 1163Tür0812551339 | m² |  | Zimmer- und Holzbauarbeiten | Türöffnung |  | 3.75 | NEW | 1163Wa 0812551342 | AllplanAttributes - Codetext: Codetext; Türanschlag: DIN L; Attributset-Objekt: OpeningElement; Positionsnummer_Text: U100; Pset_OpeningElementCommon - FireExit: no; Reference: Codetext
Türöffnung | H2 Ebene +1 | 1163Tür0812436863 | m² |  | Trockenbauarbeiten | Türöffnung |  | 3.75 | NEW | 1163Wa 0812439336 | AllplanAttributes - Bezeichnung: Türöffnung; Codetext: Codetext; Türanschlag: -; Attributset-Objekt: OpeningElement; Positionsnummer_Text: U100; Ortscode_Geschoßbezeichnung: E01; Pset_OpeningElementCommon - FireExit: no; Reference: Codetext
Türöffnung | H2 Ebene +1 | 1163Tür0812436867 | m² |  | Trockenbauarbeiten | Türöffnung |  | 3.75 | NEW | 1163Wa 0812439332 | AllplanAttributes - Bezeichnung: Türöffnung; Codetext: Codetext; Türanschlag: -; Attributset-Objekt: OpeningElement; Positionsnummer_Text: U100; Ortscode_Geschoßbezeichnung: E01; Pset_OpeningElementCommon - FireExit: no; Reference: Codetext
Türöffnung | H2 Ebene +1 | 1163Tür0812436871 | m² |  | Trockenbauarbeiten | Türöffnung |  | 3.75 | NEW | 1163Wa 0812439312 | AllplanAttributes - Bezeichnung: Türöffnung; Codetext: Codetext; Türanschlag: -; Attributset-Objekt: OpeningElement; Positionsnummer_Text: U100; Ortscode_Geschoßbezeichnung: E01; Pset_OpeningElementCommon - FireExit: no; Reference: Codetext
Türöffnung | H2 Ebene +1 | 1163Tür0812436883 | m² |  | Trockenbauarbeiten | Türöffnung |  | 3.75 | NEW | 1163Wa 0812439344 | AllplanAttributes - Bezeichnung: Türöffnung; Codetext: Codetext; Türanschlag: -; Attributset-Objekt: OpeningElement; Positionsnummer_Text: U100; Ortscode_Geschoßbezeichnung: E01; Pset_OpeningElementCommon - FireExit: no; Reference: Codetext
Türöffnung | H2 Ebene +1 | 1163Tür0812436879 | m² |  | Trockenbauarbeiten | Türöffnung |  | 3.75 | NEW | 1163Wa 0812439340 | AllplanAttributes - Bezeichnung: Türöffnung; Codetext: Codetext; Türanschlag: -; Attributset-Objekt: OpeningElement; Positionsnummer_Text: U100; Ortscode_Geschoßbezeichnung: E01; Pset_OpeningElementCommon - FireExit: no; Reference: Codetext
Türöffnung | H2 Ebene +1 | 1163Tür0812436875 | m² |  | Trockenbauarbeiten | Türöffnung |  | 3.75 | NEW | 1163Wa 0812439316 | AllplanAttributes - Bezeichnung: Türöffnung; Codetext: Codetext; Türanschlag: -; Attributset-Objekt: OpeningElement; Positionsnummer_Text: U100; Ortscode_Geschoßbezeichnung: E01; Pset_OpeningElementCommon - FireExit: no; Reference: Codetext
Türöffnung | H2 Ebene +1 | 1163Tür0812435745 | m² | 0 | Trockenbauarbeiten | Türöffnung | 0 | 3.75 | NEW | 1163Wa 0812437922 | AllplanAttributes - Codetext: Codetext; Türanschlag: -; Attributset-Objekt: OpeningElement; ash T_Schallschutz: 37 dB; Positionsnummer_Text: U100; Ortscode_Geschoßbezeichnung: E01; Pset_OpeningElementCommon - FireExit: no; Reference: Codetext
Türöffnung | H2 Ebene +1 | 1163Tür0812435798 | m² | 0 | Trockenbauarbeiten | Türöffnung | 0 | 3.75 | NEW | 1163Wa 0812437339 | AllplanAttributes - Codetext: Codetext; Türanschlag: -; Attributset-Objekt: OpeningElement; Positionsnummer_Text: U100; Ortscode_Geschoßbezeichnung: E01; Pset_OpeningElementCommon - FireExit: no; Reference: Codetext
Türöffnung | H2 Ebene +1 | 1163Tür0812435823 | m² |  | Trockenbauarbeiten | Türöffnung |  | 3.75 | NEW | 1163Wa 0812442543 | AllplanAttributes - Codetext: Codetext; Türanschlag: -; Attributset-Objekt: OpeningElement; Positionsnummer_Text: U100; Pset_OpeningElementCommon - FireExit: no; Reference: Codetext
Türöffnung | H2 Ebene +1 | 1163Tür0812446732 | m² |  | Trockenbauarbeiten | Türöffnung |  | 3.75 | NEW | 1163Wa 0812446743 | AllplanAttributes - Bezeichnung: Türöffnung; Codetext: Codetext; Türanschlag: -; Attributset-Objekt: OpeningElement; Positionsnummer_Text: U100; Ortscode_Geschoßbezeichnung: E01; Pset_OpeningElementCommon - FireExit: no; Reference: Codetext
Türöffnung | H2 Ebene +1 | 1163Tür0814484048 | m² |  | Trockenbauarbeiten | Türöffnung |  | 3.75 | NEW | 1163Wa 0812444047 | AllplanAttributes - Bezeichnung: Türöffnung; Codetext: Codetext; Türanschlag: -; Attributset-Objekt: OpeningElement; Positionsnummer_Text: U100; Ortscode_Geschoßbezeichnung: E01; Pset_OpeningElementCommon - FireExit: no; Reference: Codetext
Türöffnung | H2 Ebene +1 | 1163Tür0812496643 | m² |  | Trockenbauarbeiten | Türöffnung |  | 3.75 | NEW | 1163Wa 0812496646 | AllplanAttributes - Bezeichnung: Türöffnung; Codetext: Codetext; Türanschlag: -; Attributset-Objekt: OpeningElement; Positionsnummer_Text: U100; Ortscode_Geschoßbezeichnung: E01; Pset_OpeningElementCommon - FireExit: no; Reference: Codetext
Türöffnung | H2 Ebene +1 | 1163Tür0812436824 | m² |  | Trockenbauarbeiten | Türöffnung |  | 3.75 | NEW | 1163Wa 0812437379 | AllplanAttributes - Codetext: Codetext; Türanschlag: -; Attributset-Objekt: OpeningElement; Positionsnummer_Text: U100; Ortscode_Geschoßbezeichnung: E01; Pset_OpeningElementCommon - FireExit: no; Reference: Codetext
Türöffnung | H2 Ebene +1 | 1163Tür0814409868 | m² | 0 | Zimmer- und Holzbauarbeiten | Türöffnung | 0 | 0 | NEW | 1113Wa 0812444155 | AllplanAttributes - Türanschlag: DIN L; Positionsnummer_Text: S68
Türöffnung | H2 Ebene +1 | 1163Tür0814409867 | m² | 0 | Zimmer- und Holzbauarbeiten | Türöffnung | 0 |  | NEW | AllplanAttributes - Türanschlag: DIN L
Türöffnung | H2 Ebene +1 | 1163Tür0814409866 | m² | -30 | Zimmer- und Holzbauarbeiten | Türöffnung | 0 |  | NEW | AllplanAttributes - Türanschlag: DIN L
Türöffnung | H2 Ebene +1 | 1163Tür0814486650 | m² | 0 | Zimmer- und Holzbauarbeiten | Türöffnung | 0 | 0 | NEW | 1113Wa 0812444155 | AllplanAttributes - Türanschlag: DIN R; Positionsnummer_Text: S68
Türöffnung | H2 Ebene +1 | 1163Tür0814486649 | m² | 0 | Zimmer- und Holzbauarbeiten | Türöffnung | 0 |  | NEW | AllplanAttributes - Türanschlag: DIN R
Türöffnung | H2 Ebene +1 | 1163Tür0814486648 | m² | -30 | Zimmer- und Holzbauarbeiten | Türöffnung | 0 |  | NEW | AllplanAttributes - Türanschlag: DIN R
Türöffnung | H2 Ebene +1 | 1163Tür0812435817 | m² |  | Zimmer- und Holzbauarbeiten | Türöffnung |  | 3.75 | NEW | 1163Wa 0812437344 | AllplanAttributes - Türanschlag: DIN L; Positionsnummer_Text: U100
Türöffnung | H2 Ebene +1 | 1163Tür0812845658 | m² | 0 | Zimmer- und Holzbauarbeiten | Türöffnung | 0 | 3.75 | NEW | 1163Wa 0812845633 | AllplanAttributes - Türanschlag: DIN L; Positionsnummer_Text: U100
Türöffnung | H2 Ebene +1 | 1163Tür0812441168 | m² |  | Trockenbauarbeiten | Türöffnung |  | 3.75 | NEW | 1163Wa 0812441637 | AllplanAttributes - Bezeichnung: Türöffnung; Codetext: Codetext; Türanschlag: -; Attributset-Objekt: OpeningElement; Positionsnummer_Text: U100; Ortscode_Geschoßbezeichnung: E01; Pset_OpeningElementCommon - FireExit: no; Reference: Codetext
Türöffnung | H2 Ebene +1 | 1163Tür0812441278 | m² |  | Trockenbauarbeiten | Türöffnung |  | 3.75 | NEW | 1163Wa 0812441694 | AllplanAttributes - Bezeichnung: Türöffnung; Codetext: Codetext; Türanschlag: -; Attributset-Objekt: OpeningElement; Positionsnummer_Text: U100; Ortscode_Geschoßbezeichnung: E01; Pset_OpeningElementCommon - FireExit: no; Reference: Codetext
Türöffnung | H2 Ebene +1 | 1163Tür0812441388 | m² |  | Trockenbauarbeiten | Türöffnung |  | 3.75 | NEW | 1163Wa 0812441634 | AllplanAttributes - Bezeichnung: Türöffnung; Codetext: Codetext; Türanschlag: -; Attributset-Objekt: OpeningElement; Positionsnummer_Text: U100; Ortscode_Geschoßbezeichnung: E01; Pset_OpeningElementCommon - FireExit: no; Reference: Codetext
Türöffnung | H2 Ebene +1 | 1163Tür0812441498 | m² |  | Trockenbauarbeiten | Türöffnung |  | 3.75 | NEW | 1163Wa 0812441697 | AllplanAttributes - Bezeichnung: Türöffnung; Codetext: Codetext; Türanschlag: -; Attributset-Objekt: OpeningElement; Positionsnummer_Text: U100; Ortscode_Geschoßbezeichnung: E01; Pset_OpeningElementCommon - FireExit: no; Reference: Codetext
Türöffnung | H2 Ebene +1 | 1163Tür0812441811 | m² |  | Trockenbauarbeiten | Türöffnung |  | 3.75 | NEW | 1163Wa 0812441870 | AllplanAttributes - Bezeichnung: Türöffnung; Codetext: Codetext; Türanschlag: -; Attributset-Objekt: OpeningElement; Positionsnummer_Text: U100; Ortscode_Geschoßbezeichnung: E01; Pset_OpeningElementCommon - FireExit: no; Reference: Codetext
Türöffnung | H2 Ebene +1 | 1163Tür0812516233 | m² |  | Trockenbauarbeiten | Türöffnung |  | 3.75 | NEW | 1163Wa 0812516237 | AllplanAttributes - Codetext: Codetext; Türanschlag: -; Attributset-Objekt: OpeningElement; Positionsnummer_Text: U100; Pset_OpeningElementCommon - FireExit: no; Reference: Codetext
Türöffnung | H2 Ebene +1 | 1163Tür0814518773 | m² |  | Zimmer- und Holzbauarbeiten | Türöffnung |  | 3.75 | NEW | 1163Wa 0812441727 | AllplanAttributes - Codetext: Codetext; Türanschlag: -; Attributset-Objekt: OpeningElement; Positionsnummer_Text: U100; Pset_OpeningElementCommon - FireExit: no; Reference: Codetext
Türöffnung | H2 Ebene +1 | 1163Tür0814518762 | m² |  | Zimmer- und Holzbauarbeiten | Türöffnung |  | 3.75 | NEW | 1163Wa 0812441727 | AllplanAttributes - Codetext: Codetext; Türanschlag: -; Attributset-Objekt: OpeningElement; Positionsnummer_Text: U100; Pset_OpeningElementCommon - FireExit: no; Reference: Codetext
Türöffnung | H2 Ebene +1 | 1163Tür0814518792 | m² | 0 | Zimmer- und Holzbauarbeiten | Türöffnung | 0 |  | NEW | 1163Wa 0813777691 | AllplanAttributes - Türanschlag: -; Positionsnummer_Text: U100
Türöffnung | H2 Ebene +1 | 1163Tür0814518767 | m² | 0 | Zimmer- und Holzbauarbeiten | Türöffnung | 0 |  | NEW | 1163Wa 0813777691 | AllplanAttributes - Türanschlag: -; Positionsnummer_Text: U100
Türöffnung | H2 Ebene +1 | 1163Tür0814519937 | m² |  | Zimmer- und Holzbauarbeiten | Türöffnung |  | 3.75 | NEW | 1163Wa 0812441727 | AllplanAttributes - Codetext: Codetext; Türanschlag: -; Attributset-Objekt: OpeningElement; Positionsnummer_Text: U100; Pset_OpeningElementCommon - FireExit: no; Reference: Codetext
Türöffnung | H2 Ebene +1 | 1163Tür0814519912 | m² |  | Zimmer- und Holzbauarbeiten | Türöffnung |  | 3.75 | NEW | 1163Wa 0812441727 | AllplanAttributes - Codetext: Codetext; Türanschlag: -; Attributset-Objekt: OpeningElement; Positionsnummer_Text: U100; Pset_OpeningElementCommon - FireExit: no; Reference: Codetext
Türöffnung | H2 Ebene +1 | 1163Tür0814519909 | m² | 0 | Zimmer- und Holzbauarbeiten | Türöffnung | 0 |  | NEW | 1163Wa 0813777691 | AllplanAttributes - Türanschlag: -; Positionsnummer_Text: U100
Türöffnung | H2 Ebene +1 | 1163Tür0814519906 | m² | 0 | Zimmer- und Holzbauarbeiten | Türöffnung | 0 |  | NEW | 1163Wa 0813777691 | AllplanAttributes - Türanschlag: -; Positionsnummer_Text: U100
Türöffnung | H2 Ebene +1 | 1163Tür0814520604 | m² |  | Zimmer- und Holzbauarbeiten | Türöffnung |  | 3.75 | NEW | 1163Wa 0812441727 | AllplanAttributes - Codetext: Codetext; Türanschlag: -; Attributset-Objekt: OpeningElement; Positionsnummer_Text: U100; Pset_OpeningElementCommon - FireExit: no; Reference: Codetext
Türöffnung | H2 Ebene +1 | 1163Tür0814520599 | m² |  | Zimmer- und Holzbauarbeiten | Türöffnung |  | 3.75 | NEW | 1163Wa 0812441727 | AllplanAttributes - Codetext: Codetext; Türanschlag: -; Attributset-Objekt: OpeningElement; Positionsnummer_Text: U100; Pset_OpeningElementCommon - FireExit: no; Reference: Codetext
Türöffnung | H2 Ebene +1 | 1163Tür0814520593 | m² | 0 | Zimmer- und Holzbauarbeiten | Türöffnung | 0 |  | NEW | 1163Wa 0813777691 | AllplanAttributes - Türanschlag: -; Positionsnummer_Text: U100
Türöffnung | H2 Ebene +1 | 1163Tür0814520591 | m² | 0 | Zimmer- und Holzbauarbeiten | Türöffnung | 0 |  | NEW | 1163Wa 0813777691 | AllplanAttributes - Türanschlag: -; Positionsnummer_Text: U100
Türöffnung | H2 Ebene +1 | 1163Tür0812443194 | m² |  | Zimmer- und Holzbauarbeiten | Türöffnung |  | 3.75 | NEW | 1163Wa 0812444061 | AllplanAttributes - Codetext: Codetext; Türanschlag: DIN R; Attributset-Objekt: OpeningElement; Positionsnummer_Text: U100; Pset_OpeningElementCommon - FireExit: no; Reference: Codetext
Türöffnung | H2 Ebene +1 | 1163Tür0813775762 | m² | 0 | Zimmer- und Holzbauarbeiten | Türöffnung | 0 |  | NEW | 1163Wa 0813775742 | AllplanAttributes - Türanschlag: DIN R; Positionsnummer_Text: U100
Türöffnung | H2 Ebene +1 | 1163Tür0813775763 | m² | 0 | Zimmer- und Holzbauarbeiten | Türöffnung | 0 |  | NEW | 1163Wa 0813775743 | AllplanAttributes - Türanschlag: DIN R; Positionsnummer_Text: U100
Türöffnung | H2 Ebene +1 | 1163Tür0812446114 | m² |  | Zimmer- und Holzbauarbeiten | Türöffnung |  | 3.75 | NEW | 1163Wa 0812446773 | AllplanAttributes - Codetext: Codetext; Türanschlag: -; Attributset-Objekt: OpeningElement; Positionsnummer_Text: U100; Pset_OpeningElementCommon - FireExit: no; Reference: Codetext
Türöffnung | H2 Ebene +1 | 1163Tür0813774926 | m² | 0 | Zimmer- und Holzbauarbeiten | Türöffnung | 0 |  | NEW | 1163Wa 0813774669 | AllplanAttributes - Türanschlag: -; Positionsnummer_Text: U100
Türöffnung | H2 Ebene +1 | 1163Tür0814581567 | m² |  | Zimmer- und Holzbauarbeiten | Türöffnung |  | 3.75 | NEW | 1163Wa 0812446773 | AllplanAttributes - Codetext: Codetext; Türanschlag: -; Attributset-Objekt: OpeningElement; Positionsnummer_Text: U100; Pset_OpeningElementCommon - FireExit: no; Reference: Codetext
Türöffnung | H2 Ebene +1 | 1163Tür0814581565 | m² |  | Zimmer- und Holzbauarbeiten | Türöffnung |  | 3.75 | NEW | 1163Wa 0812446773 | AllplanAttributes - Codetext: Codetext; Türanschlag: -; Attributset-Objekt: OpeningElement; Positionsnummer_Text: U100; Pset_OpeningElementCommon - FireExit: no; Reference: Codetext
Türöffnung | H2 Ebene +1 | 1163Tür0814581574 | m² | 0 | Zimmer- und Holzbauarbeiten | Türöffnung | 0 |  | NEW | 1163Wa 0813774669 | AllplanAttributes - Türanschlag: -; Positionsnummer_Text: U100
Türöffnung | H2 Ebene +1 | 1163Tür0814581572 | m² | 0 | Zimmer- und Holzbauarbeiten | Türöffnung | 0 |  | NEW | 1163Wa 0813774669 | AllplanAttributes - Türanschlag: -; Positionsnummer_Text: U100
Türöffnung | H2 Ebene +1 | 1163Tür0814582760 | m² |  | Zimmer- und Holzbauarbeiten | Türöffnung |  | 3.75 | NEW | 1163Wa 0812446773 | AllplanAttributes - Codetext: Codetext; Türanschlag: -; Attributset-Objekt: OpeningElement; Positionsnummer_Text: U100; Pset_OpeningElementCommon - FireExit: no; Reference: Codetext
Türöffnung | H2 Ebene +1 | 1163Tür0814582740 | m² |  | Zimmer- und Holzbauarbeiten | Türöffnung |  | 3.75 | NEW | 1163Wa 0812446773 | - | AllplanAttributes - Codetext: Codetext; Türanschlag: -; Attributset-Objekt: OpeningElement; Rauchschutz: no; Selbstschließend: no; ash T_Unterschnitt: -; ash T_Zulage Schachttür: no; ash T_Dichtschließend: yes; ash T_Feststellanlage (FSA): -; ash T_nicht abschließbar: no; Positionsnummer_Text: U100; Pset_OpeningElementCommon - FireExit: no; Reference: Codetext
Türöffnung | H2 Ebene +1 | 1163Tür0814582734 | m² | 0 | Zimmer- und Holzbauarbeiten | Türöffnung | 0 |  | NEW | 1163Wa 0813774669 | AllplanAttributes - Türanschlag: -; Positionsnummer_Text: U100
Türöffnung | H2 Ebene +1 | 1163Tür0814582730 | m² | 0 | Zimmer- und Holzbauarbeiten | Türöffnung | 0 |  | NEW | 1163Wa 0813774669 | AllplanAttributes - Türanschlag: -; Positionsnummer_Text: U100
Türöffnung | H2 Ebene +1 | 1163Tür0814583431 | m² |  | Zimmer- und Holzbauarbeiten | Türöffnung |  | 3.75 | NEW | 1163Wa 0812446773 | - | AllplanAttributes - Codetext: Codetext; Türanschlag: -; Attributset-Objekt: OpeningElement; Rauchschutz: no; Selbstschließend: no; ash T_Unterschnitt: -; ash T_Zulage Schachttür: no; ash T_Dichtschließend: yes; ash T_Feststellanlage (FSA): -; ash T_nicht abschließbar: no; Positionsnummer_Text: U100; Pset_OpeningElementCommon - FireExit: no; Reference: Codetext
Türöffnung | H2 Ebene +1 | 1163Tür0814583421 | m² |  | Zimmer- und Holzbauarbeiten | Türöffnung |  | 3.75 | NEW | 1163Wa 0812446773 | AllplanAttributes - Codetext: Codetext; Türanschlag: -; Attributset-Objekt: OpeningElement; Positionsnummer_Text: U100; Pset_OpeningElementCommon - FireExit: no; Reference: Codetext
Türöffnung | H2 Ebene +1 | 1163Tür0814583419 | m² | 0 | Zimmer- und Holzbauarbeiten | Türöffnung | 0 |  | NEW | 1163Wa 0813774669 | AllplanAttributes - Türanschlag: -; Positionsnummer_Text: U100
Türöffnung | H2 Ebene +1 | 1163Tür0814583417 | m² | 0 | Zimmer- und Holzbauarbeiten | Türöffnung | 0 |  | NEW | 1163Wa 0813774669 | AllplanAttributes - Türanschlag: -; Positionsnummer_Text: U100
Türöffnung | H2 Ebene +1 | 1163Tür0812435737 | m² |  | Zimmer- und Holzbauarbeiten | Türöffnung |  | 3.75 | NEW | 1163Wa 0812447118 | AllplanAttributes - Codetext: Codetext; Türanschlag: DIN R; Attributset-Objekt: OpeningElement; Positionsnummer_Text: U100; Pset_OpeningElementCommon - FireExit: no; Reference: Codetext
Türöffnung | H2 Ebene +1 | 1163Tür0813782865 | m² | 0 | Zimmer- und Holzbauarbeiten | Türöffnung | 0 |  | NEW | 1163Wa 0813782841 | AllplanAttributes - Türanschlag: DIN R; Positionsnummer_Text: U100
Türöffnung | H2 Ebene +1 | 1163Tür0813782866 | m² | 0 | Zimmer- und Holzbauarbeiten | Türöffnung | 0 |  | NEW | 1163Wa 0813782842 | AllplanAttributes - Türanschlag: DIN R; Positionsnummer_Text: U100
Türöffnung | H2 Ebene +1 | 1163Tür0812438669 | m² |  | Trockenbauarbeiten | Türöffnung |  | 3.75 | NEW | 1163Wa 0812439875 | AllplanAttributes - Codetext: Codetext; Türanschlag: -; Attributset-Objekt: OpeningElement; Positionsnummer_Text: U100; Pset_OpeningElementCommon - FireExit: no; Reference: Codetext
Türöffnung | H2 Ebene +1 | 1163Tür0812524520 | m² |  | Trockenbauarbeiten | Türöffnung |  | 3.75 | NEW | 1163Wa 0812524524 | AllplanAttributes - Codetext: Codetext; Türanschlag: -; Attributset-Objekt: OpeningElement; Positionsnummer_Text: U100; Pset_OpeningElementCommon - FireExit: no; Reference: Codetext
Türöffnung | H2 Ebene +1 | 1163Tür0812523472 | m² |  | Zimmer- und Holzbauarbeiten | Türöffnung |  | 3.75 | NEW | 1163Wa 0812488027 | AllplanAttributes - Codetext: Codetext; Türanschlag: DIN L; Attributset-Objekt: OpeningElement; Positionsnummer_Text: U100; Pset_OpeningElementCommon - FireExit: no; Reference: Codetext
Türöffnung | H2 Ebene +1 | 1163Tür0813788853 | m² | 0 | Zimmer- und Holzbauarbeiten | Türöffnung | 0 |  | NEW | 1163Wa 0813788825 | AllplanAttributes - Türanschlag: DIN L; Positionsnummer_Text: U100
Türöffnung | H2 Ebene +1 | 1163Tür0814103218 | m² | 0 | Zimmer- und Holzbauarbeiten | Türöffnung | 0 |  | NEW | 1163Wa 0814103193 | AllplanAttributes - Türanschlag: DIN L; Positionsnummer_Text: U100
Türöffnung | H2 Ebene +1 | 1163Tür0812436192 | m² |  | Zimmer- und Holzbauarbeiten | Türöffnung |  | 3.75 | NEW | 1163Wa 0812437627 | AllplanAttributes - Codetext: Codetext; Türanschlag: DIN R; Attributset-Objekt: OpeningElement; Positionsnummer_Text: U100; Pset_OpeningElementCommon - FireExit: no; Reference: Codetext
Türöffnung | H2 Ebene +1 | 1163Tür0813790951 | m² | 0 | Zimmer- und Holzbauarbeiten | Türöffnung | 0 |  | NEW | 1163Wa 0813790835 | AllplanAttributes - Türanschlag: DIN R; Positionsnummer_Text: U100
Türöffnung | H2 Ebene +1 | 1163Tür0814620400 | m² |  | Zimmer- und Holzbauarbeiten | Türöffnung |  | 3.75 | NEW | 1163Wa 0812437627 | AllplanAttributes - Codetext: Codetext; Türanschlag: DIN L; Attributset-Objekt: OpeningElement; Positionsnummer_Text: U100; Pset_OpeningElementCommon - FireExit: no; Reference: Codetext
Türöffnung | H2 Ebene +1 | 1163Tür0814620411 | m² | 0 | Zimmer- und Holzbauarbeiten | Türöffnung | 0 |  | NEW | 1163Wa 0813790835 | AllplanAttributes - Türanschlag: DIN L; Positionsnummer_Text: U100
Türöffnung | H2 Ebene +1 | 1163Tür0812438213 | m² |  | Zimmer- und Holzbauarbeiten | Türöffnung |  | 3.75 | NEW | 1163Wa 0812438228 | - | AllplanAttributes - Codetext: Codetext; Türanschlag: -; Attributset-Objekt: OpeningElement; Rauchschutz: no; Selbstschließend: no; ash T_Unterschnitt: -; ash T_Zulage Schachttür: no; ash T_Dichtschließend: yes; ash T_Feststellanlage (FSA): -; ash T_nicht abschließbar: no; Positionsnummer_Text: U100; Pset_OpeningElementCommon - FireExit: no; Reference: Codetext
Türöffnung | H2 Ebene +1 | 1163Tür0812438217 | m² |  | Zimmer- und Holzbauarbeiten | Türöffnung |  | 3.75 | NEW | 1163Wa 0812438228 | - | AllplanAttributes - Codetext: Codetext; Türanschlag: -; Attributset-Objekt: OpeningElement; Rauchschutz: no; Selbstschließend: no; ash T_Unterschnitt: -; ash T_Zulage Schachttür: no; ash T_Dichtschließend: yes; ash T_Feststellanlage (FSA): -; ash T_nicht abschließbar: no; Positionsnummer_Text: U100; Pset_OpeningElementCommon - FireExit: no; Reference: Codetext
Türöffnung | H2 Ebene +1 | 1163Tür0813781121 | m² | 0 | Zimmer- und Holzbauarbeiten | Türöffnung | 0 |  | NEW | 1163Wa 0813780674 | AllplanAttributes - Türanschlag: -; Positionsnummer_Text: U100
Türöffnung | H2 Ebene +1 | 1163Tür0813781198 | m² | 0 | Zimmer- und Holzbauarbeiten | Türöffnung | 0 |  | NEW | 1163Wa 0813780674 | AllplanAttributes - Türanschlag: -; Positionsnummer_Text: U100
Türöffnung | H2 Ebene +1 | 1163Tür0814659980 | m² |  | Zimmer- und Holzbauarbeiten | Türöffnung |  | 3.75 | NEW | 1163Wa 0812438228 | - | AllplanAttributes - Codetext: Codetext; Türanschlag: -; Attributset-Objekt: OpeningElement; Rauchschutz: no; Selbstschließend: no; ash T_Unterschnitt: -; ash T_Zulage Schachttür: no; ash T_Dichtschließend: yes; ash T_Feststellanlage (FSA): -; ash T_nicht abschließbar: no; Positionsnummer_Text: U100; Pset_OpeningElementCommon - FireExit: no; Reference: Codetext
Türöffnung | H2 Ebene +1 | 1163Tür0814659970 | m² |  | Zimmer- und Holzbauarbeiten | Türöffnung |  | 3.75 | NEW | 1163Wa 0812438228 | - | AllplanAttributes - Codetext: Codetext; Türanschlag: -; Attributset-Objekt: OpeningElement; Rauchschutz: no; Selbstschließend: no; ash T_Unterschnitt: -; ash T_Zulage Schachttür: no; ash T_Dichtschließend: yes; ash T_Feststellanlage (FSA): -; ash T_nicht abschließbar: no; Positionsnummer_Text: U100; Pset_OpeningElementCommon - FireExit: no; Reference: Codetext
Türöffnung | H2 Ebene +1 | 1163Tür0814659957 | m² | 0 | Zimmer- und Holzbauarbeiten | Türöffnung | 0 |  | NEW | 1163Wa 0813780674 | AllplanAttributes - Türanschlag: -; Positionsnummer_Text: U100
Türöffnung | H2 Ebene +1 | 1163Tür0814659955 | m² | 0 | Zimmer- und Holzbauarbeiten | Türöffnung | 0 |  | NEW | 1163Wa 0813780674 | AllplanAttributes - Türanschlag: -; Positionsnummer_Text: U100
Türöffnung | H2 Ebene +1 | 1163Tür0814660796 | m² |  | Zimmer- und Holzbauarbeiten | Türöffnung |  | 3.75 | NEW | 1163Wa 0812438228 | - | AllplanAttributes - Codetext: Codetext; Türanschlag: -; Attributset-Objekt: OpeningElement; Rauchschutz: no; Selbstschließend: no; ash T_Unterschnitt: -; ash T_Zulage Schachttür: no; ash T_Dichtschließend: yes; ash T_Feststellanlage (FSA): -; ash T_nicht abschließbar: no; Positionsnummer_Text: U100; Pset_OpeningElementCommon - FireExit: no; Reference: Codetext
Türöffnung | H2 Ebene +1 | 1163Tür0814660776 | m² |  | Zimmer- und Holzbauarbeiten | Türöffnung |  | 3.75 | NEW | 1163Wa 0812438228 | - | AllplanAttributes - Codetext: Codetext; Türanschlag: -; Attributset-Objekt: OpeningElement; Rauchschutz: no; Selbstschließend: no; ash T_Unterschnitt: -; ash T_Zulage Schachttür: no; ash T_Dichtschließend: yes; ash T_Feststellanlage (FSA): -; ash T_nicht abschließbar: no; Positionsnummer_Text: U100; Pset_OpeningElementCommon - FireExit: no; Reference: Codetext
Türöffnung | H2 Ebene +1 | 1163Tür0814660775 | m² | 0 | Zimmer- und Holzbauarbeiten | Türöffnung | 0 |  | NEW | 1163Wa 0813780674 | AllplanAttributes - Türanschlag: -; Positionsnummer_Text: U100
Türöffnung | H2 Ebene +1 | 1163Tür0814660771 | m² | 0 | Zimmer- und Holzbauarbeiten | Türöffnung | 0 |  | NEW | 1163Wa 0813780674 | AllplanAttributes - Türanschlag: -; Positionsnummer_Text: U100
Türöffnung | H2 Ebene +1 | 1163Tür0814661292 | m² |  | Zimmer- und Holzbauarbeiten | Türöffnung |  | 3.75 | NEW | 1163Wa 0812438228 | - | AllplanAttributes - Codetext: Codetext; Türanschlag: -; Attributset-Objekt: OpeningElement; Rauchschutz: no; Selbstschließend: no; ash T_Unterschnitt: -; ash T_Zulage Schachttür: no; ash T_Dichtschließend: yes; ash T_Feststellanlage (FSA): -; ash T_nicht abschließbar: no; Positionsnummer_Text: U100; Pset_OpeningElementCommon - FireExit: no; Reference: Codetext
Türöffnung | H2 Ebene +1 | 1163Tür0814661285 | m² | 0 | Zimmer- und Holzbauarbeiten | Türöffnung | 0 |  | NEW | 1163Wa 0813780674 | AllplanAttributes - Türanschlag: -; Positionsnummer_Text: U100
Türöffnung | H2 Ebene +1 | 1163Tür0812468447 | m² |  | Trockenbauarbeiten | Türöffnung |  | 3.75 | NEW | 1163Wa 0812468455 | AllplanAttributes - Bezeichnung: Türöffnung; Codetext: Codetext; Türanschlag: -; Attributset-Objekt: OpeningElement; Positionsnummer_Text: U100; Ortscode_Geschoßbezeichnung: E01; Pset_OpeningElementCommon - FireExit: no; Reference: Codetext
Türöffnung | H2 Ebene +1 | 1163Tür0814677000 | m² |  | Zimmer- und Holzbauarbeiten | Türöffnung |  | 3.75 | NEW | 1163Wa 0812440280 | - | AllplanAttributes - Codetext: Codetext; Türanschlag: -; Attributset-Objekt: OpeningElement; Rauchschutz: no; Selbstschließend: no; ash T_Unterschnitt: -; ash T_Zulage Schachttür: no; ash T_Dichtschließend: yes; ash T_Feststellanlage (FSA): -; ash T_nicht abschließbar: no; Positionsnummer_Text: U100; Pset_OpeningElementCommon - FireExit: no; Reference: Codetext
Türöffnung | H2 Ebene +1 | 1163Tür0814677031 | m² | 0 | Zimmer- und Holzbauarbeiten | Türöffnung | 0 |  | NEW | 1163Wa 0813779695 | AllplanAttributes - Türanschlag: -; Positionsnummer_Text: U100
Türöffnung | H2 Ebene +1 | 1163Tür0814678293 | m² |  | Zimmer- und Holzbauarbeiten | Türöffnung |  | 3.75 | NEW | 1163Wa 0812440280 | - | AllplanAttributes - Codetext: Codetext; Türanschlag: -; Attributset-Objekt: OpeningElement; Rauchschutz: no; Selbstschließend: no; ash T_Unterschnitt: -; ash T_Zulage Schachttür: no; ash T_Dichtschließend: yes; ash T_Feststellanlage (FSA): -; ash T_nicht abschließbar: no; Positionsnummer_Text: U100; Pset_OpeningElementCommon - FireExit: no; Reference: Codetext
Türöffnung | H2 Ebene +1 | 1163Tür0814678278 | m² |  | Zimmer- und Holzbauarbeiten | Türöffnung |  | 3.75 | NEW | 1163Wa 0812440280 | - | AllplanAttributes - Codetext: Codetext; Türanschlag: -; Attributset-Objekt: OpeningElement; Rauchschutz: no; Selbstschließend: no; ash T_Unterschnitt: -; ash T_Zulage Schachttür: no; ash T_Dichtschließend: yes; ash T_Feststellanlage (FSA): -; ash T_nicht abschließbar: no; Positionsnummer_Text: U100; Pset_OpeningElementCommon - FireExit: no; Reference: Codetext
Türöffnung | H2 Ebene +1 | 1163Tür0814678267 | m² | 0 | Zimmer- und Holzbauarbeiten | Türöffnung | 0 |  | NEW | 1163Wa 0813779695 | AllplanAttributes - Türanschlag: -; Positionsnummer_Text: U100
Türöffnung | H2 Ebene +1 | 1163Tür0814678264 | m² | 0 | Zimmer- und Holzbauarbeiten | Türöffnung | 0 |  | NEW | 1163Wa 0813779695 | AllplanAttributes - Türanschlag: -; Positionsnummer_Text: U100
Türöffnung | H2 Ebene +1 | 1163Tür0812439020 | m² |  | Zimmer- und Holzbauarbeiten | Türöffnung |  | 3.75 | NEW | 1163Wa 0812440280 | - | AllplanAttributes - Codetext: Codetext; Türanschlag: -; Attributset-Objekt: OpeningElement; Rauchschutz: no; Selbstschließend: no; ash T_Unterschnitt: -; ash T_Zulage Schachttür: no; ash T_Dichtschließend: yes; ash T_Feststellanlage (FSA): -; ash T_nicht abschließbar: no; Positionsnummer_Text: U100; Pset_OpeningElementCommon - FireExit: no; Reference: Codetext
Türöffnung | H2 Ebene +1 | 1163Tür0812439028 | m² |  | Zimmer- und Holzbauarbeiten | Türöffnung |  | 3.75 | NEW | 1163Wa 0812440280 | - | AllplanAttributes - Codetext: Codetext; Türanschlag: -; Attributset-Objekt: OpeningElement; Rauchschutz: no; Selbstschließend: no; ash T_Unterschnitt: -; ash T_Zulage Schachttür: no; ash T_Dichtschließend: yes; ash T_Feststellanlage (FSA): -; ash T_nicht abschließbar: no; Positionsnummer_Text: U100; Pset_OpeningElementCommon - FireExit: no; Reference: Codetext
Türöffnung | H2 Ebene +1 | 1163Tür0813780235 | m² | 0 | Zimmer- und Holzbauarbeiten | Türöffnung | 0 |  | NEW | 1163Wa 0813779695 | AllplanAttributes - Türanschlag: -; Positionsnummer_Text: U100
Türöffnung | H2 Ebene +1 | 1163Tür0813779850 | m² | 0 | Zimmer- und Holzbauarbeiten | Türöffnung | 0 |  | NEW | 1163Wa 0813779695 | AllplanAttributes - Türanschlag: -; Positionsnummer_Text: U100
Türöffnung | H2 Ebene +1 | 1163Tür0814679119 | m² |  | Zimmer- und Holzbauarbeiten | Türöffnung |  | 3.75 | NEW | 1163Wa 0812440280 | - | AllplanAttributes - Codetext: Codetext; Türanschlag: -; Attributset-Objekt: OpeningElement; Rauchschutz: no; Selbstschließend: no; ash T_Unterschnitt: -; ash T_Zulage Schachttür: no; ash T_Dichtschließend: yes; ash T_Feststellanlage (FSA): -; ash T_nicht abschließbar: no; Positionsnummer_Text: U100; Pset_OpeningElementCommon - FireExit: no; Reference: Codetext
Türöffnung | H2 Ebene +1 | 1163Tür0814679114 | m² |  | Zimmer- und Holzbauarbeiten | Türöffnung |  | 3.75 | NEW | 1163Wa 0812440280 | - | AllplanAttributes - Codetext: Codetext; Türanschlag: -; Attributset-Objekt: OpeningElement; Rauchschutz: no; Selbstschließend: no; ash T_Unterschnitt: -; ash T_Zulage Schachttür: no; ash T_Dichtschließend: yes; ash T_Feststellanlage (FSA): -; ash T_nicht abschließbar: no; Positionsnummer_Text: U100; Pset_OpeningElementCommon - FireExit: no; Reference: Codetext
Türöffnung | H2 Ebene +1 | 1163Tür0814679107 | m² | 0 | Zimmer- und Holzbauarbeiten | Türöffnung | 0 |  | NEW | 1163Wa 0813779695 | AllplanAttributes - Türanschlag: -; Positionsnummer_Text: U100
Türöffnung | H2 Ebene +1 | 1163Tür0814679106 | m² | 0 | Zimmer- und Holzbauarbeiten | Türöffnung | 0 |  | NEW | 1163Wa 0813779695 | AllplanAttributes - Türanschlag: -; Positionsnummer_Text: U100
SMT | H2 Ebene +1 | 1163Tür0812442214 | m² |  | Zimmer- und Holzbauarbeiten | Türmakro |  | 3.75 | NEW | 1163Wa 0812447359 | AllplanAttributes - Material: TI-1F-UZ-D; Codetext: Codetext; Türanschlag: DIN L; Attributset-Objekt: Door; Glasanteil_berücksichtigen: 100; ash T_Zulage Schachttür: no; ash T_Dichtschließend: no; ash T_Zarge_Typ: U; ash T_Erforderl. Durchgangsbreite: 0 m; ash T_Türblatt sichtbar 2D: ja; ash T_Feststellanlage (FSA): -; ash T_nicht abschließbar: no; ash T_Tür-Nr.: Innentür 1; ash T_Blatt_Oberfläche: -; ash T_Erford. Durgangshöhe: 0 m; ash T_Blatt_Material: -; ash T_Schallschutz: -; ash T_Zarge_Material: S; ash T_Raum zugehörigkeit: BS; Positionsnummer_Text: U100; Pset_OpeningElementCommon - FireExit: no; Reference: Codetext; DoorCommon - Außenliegend: no; Feuerwiderstandsklasse: EI2 30; Rauchschutz: yes; Selbstschließend: yes
SMT | H2 Ebene +1 | 1163Tür0812442210 | m² |  | Zimmer- und Holzbauarbeiten | Türmakro |  | 3.75 | NEW | 1163Wa 0812447359 | AllplanAttributes - Material: TI-1F-UZ-D; Codetext: Codetext; Türanschlag: DIN R; Attributset-Objekt: Door; Glasanteil_berücksichtigen: 100; ash T_Zulage Schachttür: no; ash T_Dichtschließend: no; ash T_Zarge_Typ: U; ash T_Erforderl. Durchgangsbreite: 0 m; ash T_Türblatt sichtbar 2D: ja; ash T_Feststellanlage (FSA): -; ash T_nicht abschließbar: no; ash T_Tür-Nr.: Innentür 1; ash T_Blatt_Oberfläche: -; ash T_Erford. Durgangshöhe: 0 m; ash T_Blatt_Material: -; ash T_Schallschutz: -; ash T_Zarge_Material: S; ash T_Raum zugehörigkeit: BS; Positionsnummer_Text: U100; Pset_OpeningElementCommon - FireExit: no; Reference: Codetext; DoorCommon - Außenliegend: no; Feuerwiderstandsklasse: EI2 30; Rauchschutz: yes; Selbstschließend: yes
SMT | H2 Ebene +1 | 1163Tür0814680573 | m² | 0 | Zimmer- und Holzbauarbeiten | Türöffnung | 0 |  | NEW | AllplanAttributes - Türanschlag: DIN L
SMT | H2 Ebene +1 | 1163Tür0814680649 | m² | 0 | Zimmer- und Holzbauarbeiten | Türöffnung | 0 |  | NEW | AllplanAttributes - Türanschlag: DIN R
Türöffnung | H2 Ebene +1 | 1163Tür0812447345 | m² |  | Zimmer- und Holzbauarbeiten | Türöffnung |  | 3.75 | NEW | 1163Wa 0812447378 | AllplanAttributes - Codetext: Codetext; Türanschlag: DIN R; Attributset-Objekt: OpeningElement; Positionsnummer_Text: U100; Pset_OpeningElementCommon - FireExit: no; Reference: Codetext
Türöffnung | H2 Ebene +1 | 1163Tür0813792263 | m² | 0 | Zimmer- und Holzbauarbeiten | Türöffnung | 0 |  | NEW | 1163Wa 0813792253 | AllplanAttributes - Türanschlag: DIN R; Positionsnummer_Text: U100
Türöffnung | H2 Ebene +1 | 1163Tür0814681083 | m² | 0 | Zimmer- und Holzbauarbeiten | Türöffnung | 0 |  | NEW | AllplanAttributes - Türanschlag: DIN R
Fensteröffnung | H2 Ebene +1 | 1163Fen0814705927 | m² |  | Fensterarbeiten | Fensteröffnung |  | 3.75 |  | 1163Wa 0812437264 | AllplanAttributes - Positionsnummer_Text: U100; ash_W_Trockenbau_Qualitäten: 1
Fensteröffnung | H2 Ebene +1 | 1163Fen0814705980 | m² |  | Fensterarbeiten | Fensteröffnung |  | 3.75 |  | 1163Wa 0812437264 | AllplanAttributes - Positionsnummer_Text: U100; ash_W_Trockenbau_Qualitäten: 1
Fensteröffnung | H2 Ebene +1 | 1163Fen0814705976 | m² |  | Fensterarbeiten | Fensteröffnung |  | 3.75 |  | 1163Wa 0812437264 | AllplanAttributes - Positionsnummer_Text: U100
Fensteröffnung | H2 Ebene +1 | 1163Fen0814705978 | m² |  | Fensterarbeiten | Fensteröffnung |  | 3.75 |  | 1163Wa 0812437264 | AllplanAttributes - Positionsnummer_Text: U100
Türöffnung | H2 Ebene +1 | 1163Tür0812440680 | m² |  | Zimmer- und Holzbauarbeiten | Türöffnung |  | 3.75 | NEW | 1163Wa 0812441727 | AllplanAttributes - Codetext: Codetext; Türanschlag: -; Attributset-Objekt: OpeningElement; Positionsnummer_Text: U100; Pset_OpeningElementCommon - FireExit: no; Reference: Codetext
Türöffnung | H2 Ebene +1 | 1163Tür0813778059 | m² | 0 | Zimmer- und Holzbauarbeiten | Türöffnung | 0 |  | NEW | 1163Wa 0813777691 | AllplanAttributes - Türanschlag: -; Positionsnummer_Text: U100
Türöffnung | H2 Ebene +1 | 1163Tür0814723851 | m² |  | Zimmer- und Holzbauarbeiten | Türöffnung |  | 3.75 | NEW | 1163Wa 0812444061 | AllplanAttributes - Codetext: Codetext; Türanschlag: DIN R; Attributset-Objekt: OpeningElement; Positionsnummer_Text: U100; Pset_OpeningElementCommon - FireExit: no; Reference: Codetext
Türöffnung | H2 Ebene +1 | 1163Tür0814723850 | m² |  | Zimmer- und Holzbauarbeiten | Türöffnung |  | 3.75 | NEW | 1163Wa 0812444061 | AllplanAttributes - Codetext: Codetext; Türanschlag: DIN L; Attributset-Objekt: OpeningElement; Positionsnummer_Text: U100; Pset_OpeningElementCommon - FireExit: no; Reference: Codetext
Türöffnung | H2 Ebene +1 | 1163Tür0814723848 | m² | 0 | Zimmer- und Holzbauarbeiten | Türöffnung | 0 |  | NEW | 1163Wa 0813775742 | AllplanAttributes - Türanschlag: DIN R; Positionsnummer_Text: U100
Türöffnung | H2 Ebene +1 | 1163Tür0814723846 | m² | 0 | Zimmer- und Holzbauarbeiten | Türöffnung | 0 |  | NEW | 1163Wa 0813775742 | AllplanAttributes - Türanschlag: DIN L; Positionsnummer_Text: U100
Türöffnung | H2 Ebene +1 | 1163Tür0814723845 | m² | 0 | Zimmer- und Holzbauarbeiten | Türöffnung | 0 |  | NEW | 1163Wa 0813775743 | AllplanAttributes - Türanschlag: DIN R; Positionsnummer_Text: U100
Türöffnung | H2 Ebene +1 | 1163Tür0814723844 | m² | 0 | Zimmer- und Holzbauarbeiten | Türöffnung | 0 |  | NEW | 1163Wa 0813775743 | AllplanAttributes - Türanschlag: DIN L; Positionsnummer_Text: U100
Türöffnung | H2 Ebene +1 | 1163Tür0814566089 | m² |  | Zimmer- und Holzbauarbeiten | Türöffnung |  | 3.75 | NEW | 1163Wa 0812444061 | AllplanAttributes - Codetext: Codetext; Türanschlag: DIN R; Attributset-Objekt: OpeningElement; Positionsnummer_Text: U100; Pset_OpeningElementCommon - FireExit: no; Reference: Codetext
Türöffnung | H2 Ebene +1 | 1163Tür0814566093 | m² | 0 | Zimmer- und Holzbauarbeiten | Türöffnung | 0 |  | NEW | 1163Wa 0813775742 | AllplanAttributes - Türanschlag: DIN R; Positionsnummer_Text: U100
Türöffnung | H2 Ebene +1 | 1163Tür0814566094 | m² | 0 | Zimmer- und Holzbauarbeiten | Türöffnung | 0 |  | NEW | 1163Wa 0813775743 | AllplanAttributes - Türanschlag: DIN R; Positionsnummer_Text: U100
Türöffnung | H2 Ebene +1 | 1163Tür0812435741 | m² | 0 | Trockenbauarbeiten | Türöffnung | 0 | 3.75 | NEW | 1163Wa 0812446956 | AllplanAttributes - Codetext: Codetext; Türanschlag: -; Attributset-Objekt: OpeningElement; Positionsnummer_Text: U100; Ortscode_Geschoßbezeichnung: E01; Pset_OpeningElementCommon - FireExit: no; Reference: Codetext
Fensteröffnung | H2 Ebene +1 | 1163Fen0814612131 | m² |  | Fensterarbeiten | Fensteröffnung |  | 3.75 |  | 1163Wa 0812437264 | AllplanAttributes - Positionsnummer_Text: U100
Fensteröffnung | H2 Ebene +1 | 1163Fen0814612132 | m² | 0 | Fensterarbeiten | Fensteröffnung | 0 |  | NEW | 1163Wa 0813785151 | AllplanAttributes - Positionsnummer_Text: U100
Fensteröffnung | H2 Ebene +1 | 1163Fen0814612133 | m² | 0 | Fensterarbeiten | Fensteröffnung | 0 |  | NEW | 1163Wa 0813785152 | AllplanAttributes - ash D_Detailverweis: D1833; Positionsnummer_Text: U100
Türöffnung | H2 Ebene +1 | 1163Tür0812480017 | m² |  | Zimmer- und Holzbauarbeiten | Türöffnung |  | 3.75 |  | 1163Wa 0812440294 | AllplanAttributes - Codetext: Codetext; Türanschlag: -; Positionsnummer_Text: U100; Pset_OpeningElementCommon - FireExit: no; Reference: Codetext
Türöffnung | H2 Ebene +1 | 1163Tür0812517822 | m² |  | Zimmer- und Holzbauarbeiten | Türöffnung |  | 3.75 | NEW | 1163Wa 0812446937 | AllplanAttributes - Türanschlag: -; Positionsnummer_Text: U100
Türöffnung | H2 Ebene +1 | 1163Tür0812551353 | m² |  | Zimmer- und Holzbauarbeiten | Türöffnung |  | 3.75 | NEW | 1163Wa 0812551363 | AllplanAttributes - Codetext: Codetext; Türanschlag: DIN L; Attributset-Objekt: OpeningElement; Positionsnummer_Text: U100; Pset_OpeningElementCommon - FireExit: no; Reference: Codetext
Türöffnung | H2 Ebene +1 | 1163Tür0814104897 | m² | 0 | Zimmer- und Holzbauarbeiten | Türöffnung | 0 |  | NEW | 1163Wa 0814104879 | AllplanAttributes - Türanschlag: DIN L; Positionsnummer_Text: U100
Türöffnung | H2 Ebene +1 | 1163Tür0812442292 | m² |  | Zimmer- und Holzbauarbeiten | Türöffnung |  | 3.75 | NEW | 1163Wa 0812443005 | AllplanAttributes - Codetext: Codetext; Türanschlag: DIN R; Attributset-Objekt: OpeningElement; Positionsnummer_Text: U100; Pset_OpeningElementCommon - FireExit: no; Reference: Codetext
Türöffnung | H2 Ebene +1 | 1163Tür0813777074 | m² | 0 | Zimmer- und Holzbauarbeiten | Türöffnung | 0 |  | NEW | 1163Wa 0813777055 | AllplanAttributes - Türanschlag: DIN R; Positionsnummer_Text: U100
Türöffnung | H2 Ebene +1 | 1163Tür0814537101 | m² |  | Zimmer- und Holzbauarbeiten | Türöffnung |  | 3.75 | NEW | 1163Wa 0812443005 | AllplanAttributes - Codetext: Codetext; Türanschlag: DIN L; Attributset-Objekt: OpeningElement; Positionsnummer_Text: U100; Pset_OpeningElementCommon - FireExit: no; Reference: Codetext
Türöffnung | H2 Ebene +1 | 1163Tür0814537102 | m² | 0 | Zimmer- und Holzbauarbeiten | Türöffnung | 0 |  | NEW | 1163Wa 0813777055 | AllplanAttributes - Türanschlag: DIN L; Positionsnummer_Text: U100
Türöffnung | H2 Ebene +1 | 1163Tür0812551380 | m² |  | Metallbau-, Schlosserarbeiten | Türmakro |  | 3.75 | NEW | 1163Wa 0812551371 | AllplanAttributes - Material: TI-1F-UZ-D; Codetext: Codetext; Türanschlag: DIN R; Attributset-Objekt: Door; Positionsnummer: 1; V6: 0 m; V7: 0 m; V8: 0 m; V9: 0; Glasanteil_berücksichtigen: 100; ash T_Unterschnitt: -; ash T_Zulage Schachttür: no; ash T_Dichtschließend: yes; ash T_Zarge_Typ: U; ash T_Erforderl. Durchgangsbreite: 0 m; ash T_Türblatt sichtbar 2D: ja; ash T_Feststellanlage (FSA): -; ash T_nicht abschließbar: no; ash T_Blatt_Oberfläche: -; ash T_Erford. Durgangshöhe: 0 m; ash T_Blatt_Material: -; ash T_Schallschutz: -; ash T_Zarge_Material: S; ash T_Raum zugehörigkeit: BS; Positionsnummer_Text: U100; Pset_OpeningElementCommon - FireExit: no; Reference: Codetext; DoorCommon - Außenliegend: no; Feuerwiderstandsklasse: -; Rauchschutz: no; Selbstschließend: no
Türöffnung | H2 Ebene +1 | 1163Tür0814105110 | m² | 0 | Metallbau-, Schlosserarbeiten | Türöffnung | 0 |  | NEW | 1163Wa 0814105097 | AllplanAttributes - Türanschlag: DIN R; Positionsnummer_Text: U100
Türöffnung | H2 Ebene +1 | 1163Tür0812655394 | m² |  | Trockenbauarbeiten | Türöffnung |  | 3.75 | NEW | 1163Wa 0812655406 | AllplanAttributes - Codetext: Codetext; Türanschlag: DIN L; Attributset-Objekt: OpeningElement; Positionsnummer_Text: U100; Pset_OpeningElementCommon - FireExit: no; Reference: Codetext
Türöffnung | H2 Ebene +1 | 1163Tür0814105811 | m² | 0 | Trockenbauarbeiten | Türöffnung | 0 |  | NEW | 1163Wa 0814105800 | AllplanAttributes - Türanschlag: DIN L; Positionsnummer_Text: U100
Türöffnung | H2 Ebene +1 | 1163Tür0812440948 | m² |  | Trockenbauarbeiten | Türöffnung |  | 3.75 | NEW | 1163Wa 0812441691 | AllplanAttributes - Bezeichnung: Türöffnung; Codetext: Codetext; Türanschlag: -; Attributset-Objekt: OpeningElement; Positionsnummer_Text: U100; Ortscode_Geschoßbezeichnung: E01; Pset_OpeningElementCommon - FireExit: no; Reference: Codetext
Türöffnung | H2 Ebene +1 | 1163Tür0812441058 | m² |  | Trockenbauarbeiten | Türöffnung |  | 3.75 | NEW | 1163Wa 0812441640 | AllplanAttributes - Bezeichnung: Türöffnung; Codetext: Codetext; Türanschlag: -; Attributset-Objekt: OpeningElement; Positionsnummer_Text: U100; Ortscode_Geschoßbezeichnung: E01; Pset_OpeningElementCommon - FireExit: no; Reference: Codetext
Türöffnung | H2 Ebene +1 | 1163Tür0812440699 | m² |  | Trockenbauarbeiten | Türöffnung |  | 3.75 | NEW | 1163Wa 0812440861 | AllplanAttributes - Türanschlag: -; Positionsnummer_Text: U100
Türöffnung | H2 Ebene +1 | 1163Tür0812443000 | m² |  | Zimmer- und Holzbauarbeiten | Türöffnung |  | 3.75 | NEW | 1163Wa 0812500751 | AllplanAttributes - Türanschlag: -; Positionsnummer_Text: U100
Türöffnung | H2 Ebene +1 | 1163Tür0812435720 | m² |  | Trockenbauarbeiten | Türöffnung |  | 3.75 | NEW | 1163Wa 0812444170 | AllplanAttributes - Codetext: Codetext; Türanschlag: -; Attributset-Objekt: OpeningElement; Positionsnummer_Text: U100; Pset_OpeningElementCommon - FireExit: no; Reference: Codetext
Fensteröffnung | H2 Ebene +1 | 1163Fen0814111849 | m² |  | Fensterarbeiten | Fensteröffnung |  | 3.75 |  | 1163Wa 0812437264 | AllplanAttributes - Positionsnummer_Text: U100
Türöffnung | H2 Ebene +1 | 1163Tür0812435693 | m² |  | Trockenbauarbeiten | Türöffnung |  | 3.75 | NEW | 1163Wa 0812442525 | AllplanAttributes - Codetext: Codetext; Türanschlag: -; Attributset-Objekt: OpeningElement; Positionsnummer_Text: U100; Ortscode_Geschoßbezeichnung: E01; Pset_OpeningElementCommon - FireExit: no; Reference: Codetext
Türöffnung | H2 Ebene +1 | 1163Tür0814705820 | m² |  | Zimmer- und Holzbauarbeiten | Türöffnung |  | 3.75 | NEW | 1163Wa 0814107886 | AllplanAttributes - Türanschlag: -; Positionsnummer_Text: U100
Fensteröffnung | H2 Ebene +1 | 1163Fen0814705925 | m² |  | Fensterarbeiten | Fensteröffnung |  | 3.75 |  | 1163Wa 0812437264 | AllplanAttributes - Positionsnummer_Text: U100; ash_W_Trockenbau_Qualitäten: 1
Fensteröffnung | H2 Ebene +1 | 1163Fen0814705929 | m² |  | Fensterarbeiten | Fensteröffnung |  | 3.75 |  | 1163Wa 0812437264 | AllplanAttributes - Positionsnummer_Text: U100
Türöffnung | H2 Ebene +1 | 1163Tür0814007547 | m² |  | Zimmer- und Holzbauarbeiten | Türöffnung |  | 3.75 | NEW | 1163Wa 0814007554 | AllplanAttributes - Türanschlag: -; Positionsnummer_Text: U100
Türöffnung | H2 Ebene +1 | 1163Tür0813982057 | m² |  | Zimmer- und Holzbauarbeiten | Türöffnung |  | 3.75 | NEW | 1163Wa 0813982065 | AllplanAttributes - Türanschlag: -; Positionsnummer_Text: U100
Fensteröffnung | H2 Ebene +1 | 1163Fen0814705957 | m² |  | Fensterarbeiten | Fensteröffnung |  | 3.75 |  | 1163Wa 0812437264 | EI 30 | AllplanAttributes - Glasanteil_berücksichtigen: 100; Positionsnummer_Text: U100
Fensteröffnung | H2 Ebene +1 | 1163Fen0814705908 | m² |  | Fensterarbeiten | Fensteröffnung |  | 3.75 |  | 1163Wa 0812437264 | AllplanAttributes - Positionsnummer_Text: U100
Fensteröffnung | H2 Ebene +1 | 1163Fen0814705902 | m² |  | Fensterarbeiten | Fensteröffnung |  | 3.75 |  | 1163Wa 0812437264 | AllplanAttributes - Positionsnummer_Text: U100
Türöffnung | H2 Ebene +1 | 1163Tür0814706069 | m² |  | Zimmer- und Holzbauarbeiten | Türöffnung |  | 3.75 | NEW | 1163Wa 0814107886 | AllplanAttributes - Türanschlag: -; Positionsnummer_Text: U100
Türöffnung | H2 Ebene +1 | 1163Tür0812508939 | m² |  | Zimmer- und Holzbauarbeiten | Türöffnung |  | 3.75 | NEW | 1163Wa 0812508669 | AllplanAttributes - Türanschlag: -; Positionsnummer_Text: U100
Türöffnung | H2 Ebene +1 | 1163Tür0812435685 | m² |  | Trockenbauarbeiten | Türöffnung |  | 3.75 | NEW | 1163Wa 0812446900 | AllplanAttributes - Bezeichnung: Türöffnung; Codetext: Codetext; Türanschlag: -; Attributset-Objekt: OpeningElement; Positionsnummer_Text: U100; Ortscode_Geschoßbezeichnung: E01; Pset_OpeningElementCommon - FireExit: no; Reference: Codetext
Türöffnung | H2 Ebene +1 | 1163Tür0812435681 | m² |  | Trockenbauarbeiten | Türöffnung |  | 3.75 | NEW | 1163Wa 0812446900 | AllplanAttributes - Bezeichnung: Türöffnung; Codetext: Codetext; Türanschlag: -; Attributset-Objekt: OpeningElement; Positionsnummer_Text: U100; Ortscode_Geschoßbezeichnung: E01; Pset_OpeningElementCommon - FireExit: no; Reference: Codetext
Fensteröffnung | H2 Ebene +1 | 1163Fen0814112839 | m² | 0 | Fensterarbeiten | Fensteröffnung | 0 | 3.75 |  | 1163Wa 0812437264 | AllplanAttributes - Positionsnummer_Text: U100
Türöffnung | H2 Ebene +1 | 1163Tür0812833390 | m² |  | Trockenbauarbeiten | Türöffnung |  | 3.75 | NEW | 1163Wa 0812833408 | AllplanAttributes - Codetext: Codetext; Türanschlag: -; Attributset-Objekt: OpeningElement; Positionsnummer_Text: U100; Ortscode_Geschoßbezeichnung: E01; Pset_OpeningElementCommon - FireExit: no; Reference: Codetext
Türöffnung | H2 Ebene +1 | 1163Tür0813928975 | m² |  | Trockenbauarbeiten | Türöffnung |  | 3.75 | NEW | 1163Wa 0813929020 | AllplanAttributes - Türanschlag: -; Positionsnummer_Text: U100
Türöffnung | H2 Ebene +1 | 1163Tür0812436063 | m² |  | Trockenbauarbeiten | Türöffnung |  | 3.75 | NEW | 1163Wa 0812437372 | AllplanAttributes - Türanschlag: -; Positionsnummer_Text: U100
Türöffnung | H2 Ebene +1 | 1163Tür0812438947 | m² |  | Trockenbauarbeiten | Türöffnung |  | 3.75 | NEW | 1163Wa 0812440268 | AllplanAttributes - Türanschlag: -; Positionsnummer_Text: U100
Türöffnung | H2 Ebene +1 | 1163Tür0814385261 | m² |  | Zimmer- und Holzbauarbeiten | Türöffnung |  | 3.75 |  | 1163Wa 0812439834 | AllplanAttributes - Codetext: Codetext; Türanschlag: -; Positionsnummer_Text: U100; Pset_OpeningElementCommon - FireExit: no; Reference: Codetext
Türöffnung | H2 Ebene +1 | 1163Tür0814418663 | m² |  | Trockenbauarbeiten | Türöffnung |  | 3.75 | NEW | 1163Wa 0812654446 | AllplanAttributes - Codetext: Codetext; Türanschlag: DIN R; Attributset-Objekt: OpeningElement; Positionsnummer_Text: U100; Pset_OpeningElementCommon - FireExit: no; Reference: Codetext
Türöffnung | H2 Ebene +1 | 1163Tür0814418669 | m² | 0 | Trockenbauarbeiten | Türöffnung | 0 |  | NEW | 1163Wa 0814105489 | AllplanAttributes - Türanschlag: DIN R; Positionsnummer_Text: U100
Türöffnung | H2 Ebene +1 | 1163Tür0813903337 | m² |  | Trockenbauarbeiten | Türöffnung |  | 3.75 | NEW | 1163Wa 0813903353 | AllplanAttributes - Türanschlag: -; Positionsnummer_Text: U100
Türöffnung | H2 Ebene +1 | 1163Tür0814454120 | m² | 0 | Zimmer- und Holzbauarbeiten | Türöffnung | 0 | 0 | NEW | 1113Wa 0812447364 | E 60 | AllplanAttributes - Türanschlag: -; Text1: 15b; Positionsnummer_Text: S68
Türöffnung | H2 Ebene +1 | 1163Tür0814454053 | m² | 0 | Zimmer- und Holzbauarbeiten | Türöffnung | 0 | 0 | NEW | 1113Wa 0812447364 | E 60 | AllplanAttributes - Türanschlag: -; Text1: 15b; Positionsnummer_Text: S68
Türöffnung | H2 Ebene +1 | 1163Tür0812943633 | m² |  | Trockenbauarbeiten | Türöffnung |  | 3.75 | NEW | 1163Wa 0812447364 | EI2 30 | AllplanAttributes - Codetext: Codetext; Türanschlag: DIN R; Attributset-Objekt: OpeningElement; Rauchschutz: yes; Selbstschließend: yes; ash T_Zulage Schachttür: no; ash T_Dichtschließend: no; ash T_Feststellanlage (FSA): -; ash T_nicht abschließbar: no; Positionsnummer_Text: U100; Pset_OpeningElementCommon - FireExit: no; Reference: Codetext
Türöffnung | H2 Ebene +1 | 1163Tür0814454119 | m² | -170 | Zimmer- und Holzbauarbeiten | Türöffnung | 0 | 0 | NEW | 1113Wa 0812843889 | AllplanAttributes - Türanschlag: -; Positionsnummer_Text: S68
Türöffnung | H2 Ebene +1 | 1163Tür0814454052 | m² | -170 | Zimmer- und Holzbauarbeiten | Türöffnung | 0 | 0 | NEW | 1113Wa 0812843889 | AllplanAttributes - Türanschlag: -; Positionsnummer_Text: S68
Türöffnung | H2 Ebene +1 | 1163Tür0812943632 | m² | 0 | Trockenbauarbeiten | Türöffnung | 0 | 0 | NEW | 1163Wa 0812843889 | AllplanAttributes - Türanschlag: DIN R; ash T_Feststellanlage (FSA): -; Positionsnummer_Text: U100
Türöffnung | H2 Ebene +1 | 1163Tür0812435739 | m² |  | Trockenbauarbeiten | Türöffnung |  | 3.75 | NEW | 1163Wa 0812447073 | AllplanAttributes - Bezeichnung: Türöffnung; Codetext: Codetext; Türanschlag: -; Attributset-Objekt: OpeningElement; Positionsnummer_Text: U100; Ortscode_Geschoßbezeichnung: E01; Pset_OpeningElementCommon - FireExit: no; Reference: Codetext
Türöffnung | H2 Ebene +1 | 1163Tür0814777927 | m² |  | Zimmer- und Holzbauarbeiten | Türöffnung |  | 3.75 | NEW | 1163Wa 0812447387 | - | AllplanAttributes - Codetext: Codetext; Türanschlag: DIN R; Attributset-Objekt: OpeningElement; Rauchschutz: no; Selbstschließend: no; ash T_Unterschnitt: -; ash T_Zulage Schachttür: no; ash T_Dichtschließend: yes; ash T_Zarge_Typ: U; ash T_Erforderl. Durchgangsbreite: 0 m; ash T_Türblatt sichtbar 2D: ja; ash T_Feststellanlage (FSA): -; ash T_nicht abschließbar: no; ash T_Blatt_Oberfläche: -; ash T_Erford. Durgangshöhe: 0 m; ash T_Blatt_Material: -; ash T_Schallschutz: -; ash T_Zarge_Material: S; Positionsnummer_Text: U100; Pset_OpeningElementCommon - FireExit: no; Reference: Codetext
Türöffnung | H2 Ebene +1 | 1163Tür0814777926 | m² | 0 | Zimmer- und Holzbauarbeiten | Türöffnung | 0 |  | NEW | AllplanAttributes - Türanschlag: DIN R; Positionsnummer_Text: U100
Türöffnung | H2 Ebene +1 | 1163Tür0812447092 | m² |  | Trockenbauarbeiten | Türöffnung |  | 3.75 | NEW | 1163Wa 0812447098 | AllplanAttributes - Bezeichnung: Türöffnung; Codetext: Codetext; Türanschlag: -; Attributset-Objekt: OpeningElement; Positionsnummer_Text: U100; Ortscode_Geschoßbezeichnung: E01; Pset_OpeningElementCommon - FireExit: no; Reference: Codetext
Türöffnung | H2 Ebene +1 | 1163Tür0812551337 | m² |  | Zimmer- und Holzbauarbeiten | Türöffnung |  | 3.75 | NEW | 1163Wa 0812551376 | AllplanAttributes - Codetext: Codetext; Türanschlag: DIN L; Attributset-Objekt: OpeningElement; Positionsnummer_Text: U100; Pset_OpeningElementCommon - FireExit: no; Reference: Codetext
Türöffnung | H2 Ebene +1 | 1163Tür0813787847 | m² | 0 | Zimmer- und Holzbauarbeiten | Türöffnung | 0 |  | NEW | 1163Wa 0813787831 | AllplanAttributes - Türanschlag: DIN L; Positionsnummer_Text: U100
Türöffnung | H2 Ebene +1 | 1163Tür0812553538 | m² |  | Zimmer- und Holzbauarbeiten | Türöffnung |  | 3.75 | NEW | 1163Wa 0812553865 | AllplanAttributes - Codetext: Codetext; Türanschlag: DIN R; Attributset-Objekt: OpeningElement; Positionsnummer_Text: U100; Pset_OpeningElementCommon - FireExit: no; Reference: Codetext
Türöffnung | H2 Ebene +1 | 1163Tür0812553540 | m² |  | Zimmer- und Holzbauarbeiten | Türöffnung |  | 3.75 | NEW | 1163Wa 0812553865 | AllplanAttributes - Codetext: Codetext; Türanschlag: DIN R; Attributset-Objekt: OpeningElement; Positionsnummer_Text: U100; Pset_OpeningElementCommon - FireExit: no; Reference: Codetext
Türöffnung | H2 Ebene +1 | 1163Tür0814100947 | m² | 0 | Zimmer- und Holzbauarbeiten | Türöffnung | 0 |  | NEW | 1163Wa 0814100809 | AllplanAttributes - Türanschlag: DIN R; Positionsnummer_Text: U100
Türöffnung | H2 Ebene +1 | 1163Tür0814100826 | m² | 0 | Zimmer- und Holzbauarbeiten | Türöffnung | 0 |  | NEW | 1163Wa 0814100809 | AllplanAttributes - Türanschlag: DIN R; Positionsnummer_Text: U100
Türöffnung | H2 Ebene +1 | 1163Tür0812438673 | m² |  | Betonarbeiten | Türöffnung |  | 3.75 | NEW | 1163Wa 0812438684 | REI 90-A1 | AllplanAttributes - Material: WA-STB; Tragendes Bauteil: yes; Brandabschnittsdefinierendes Bauteil: no; Außenliegend: yes; U-Wert: 0; Schallschutzklasse: 0; Codetext: Codetext; Türanschlag: -; Typ: 0; Brennbares Material: no; Brandverhalten: 0; Brandschutzklasse: A; Positionsnummer_Text: U100; Pset_OpeningElementCommon - Reference: Codetext
Türöffnung | H2 Ebene +1 | 1163Tür0812446140 | m² |  | Betonarbeiten | Türöffnung |  | 3.75 | NEW | 1163Wa 0812446151 | REI 90-A1 | AllplanAttributes - Material: WA-STB; Tragendes Bauteil: yes; Brandabschnittsdefinierendes Bauteil: no; Außenliegend: yes; U-Wert: 0; Schallschutzklasse: 0; Codetext: Codetext; Türanschlag: -; Typ: 0; Brennbares Material: no; Brandverhalten: 0; Brandschutzklasse: A; Positionsnummer_Text: U100; Pset_OpeningElementCommon - Reference: Codetext
Türöffnung | H2 Ebene +1 | 1163Tür0814787065 | m² |  | Zimmer- und Holzbauarbeiten | Türöffnung |  | 3.75 | NEW | 1163Wa 0812447355 | AllplanAttributes - Codetext: Codetext; Türanschlag: DIN L; Attributset-Objekt: OpeningElement; Positionsnummer_Text: U100; Pset_OpeningElementCommon - FireExit: no; Reference: Codetext
Türöffnung | H2 Ebene +1 | 1163Tür0814787064 | m² | 0 | Zimmer- und Holzbauarbeiten | Türöffnung | 0 |  | NEW | 1163Wa 0814078116 | AllplanAttributes - Türanschlag: DIN L; Positionsnummer_Text: U100
Türöffnung | H2 Ebene +1 | 1163Tür0814787177 | m² | 0 | Zimmer- und Holzbauarbeiten | Türöffnung | 0 |  | NEW | AllplanAttributes - Türanschlag: DIN L
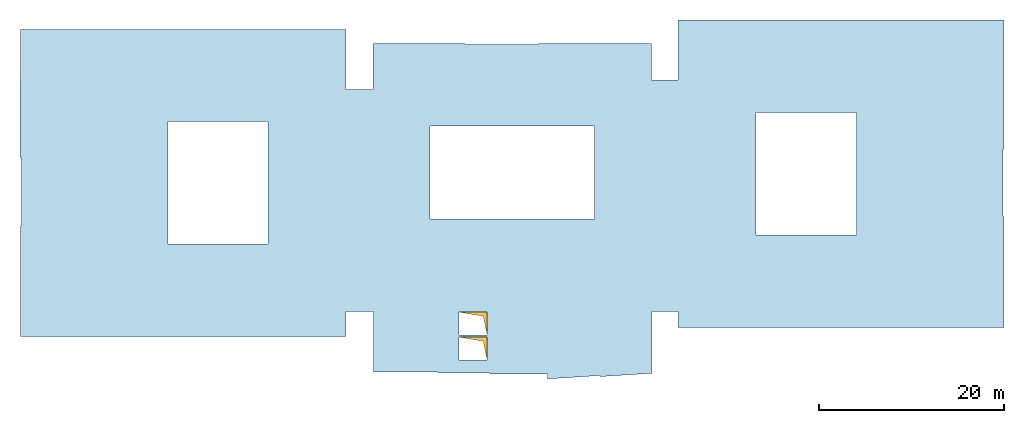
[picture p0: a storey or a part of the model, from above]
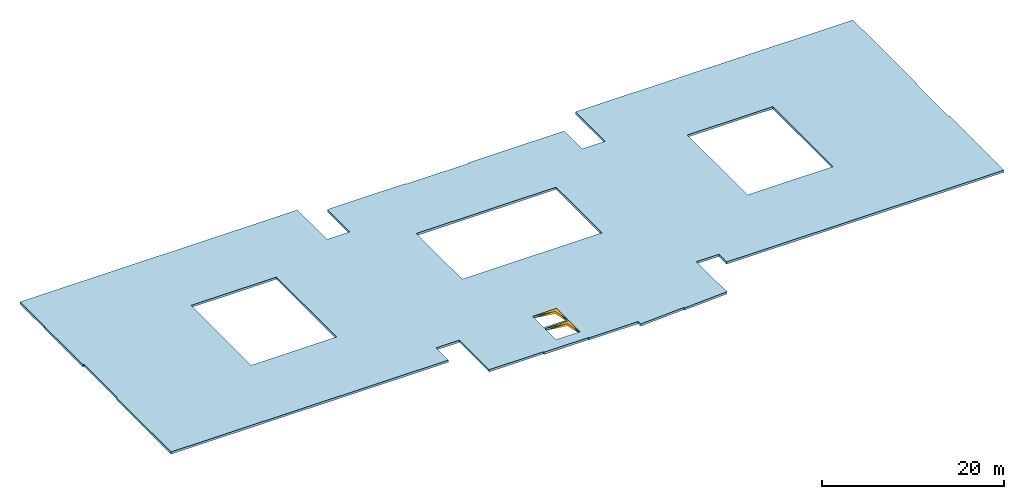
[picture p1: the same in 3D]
Properties of the parts of a building model (IFC4), part 39 of 80

# IfcOpeningElement: Opening (3497)
Name | In | Allright_Bauteil_ID | Abrechnungsart | Versatz_oben | Gewerk | Objektname | Versatz_unten | OKFF | Status | P_ID | AllplanAttributes, Feuerwiderstandsklasse | Sicherheitsklasse | g-Wert
Türöffnung | H2 Ebene +1 | 1163Tür0812531632 | m² |  | Zimmer- und Holzbauarbeiten | Türöffnung |  | 3.75 | NEW | 1163Wa 0812531640 | REI 90-A1 | AllplanAttributes - Material: WA-STB; Tragendes Bauteil: yes; Brandabschnittsdefinierendes Bauteil: no; Außenliegend: yes; U-Wert: 0; Schallschutzklasse: 0; Codetext: Codetext; Türanschlag: -; Typ: 0; Brennbares Material: no; Brandverhalten: 0; Brandschutzklasse: A; Positionsnummer_Text: U100; Pset_OpeningElementCommon - Reference: Codetext
Türöffnung | H2 Ebene +1 | 1163Tür0812440004 | m² |  | Zimmer- und Holzbauarbeiten | Türöffnung |  | 3.75 | NEW | 1163Wa 0812440009 | REI 90-A1 | AllplanAttributes - Material: WA-STB; Tragendes Bauteil: yes; Brandabschnittsdefinierendes Bauteil: no; Außenliegend: yes; U-Wert: 0; Schallschutzklasse: 0; Codetext: Codetext; Türanschlag: -; Typ: 0; Brennbares Material: no; Brandverhalten: 0; Brandschutzklasse: A; Positionsnummer_Text: U100; Pset_OpeningElementCommon - Reference: Codetext
Fensteröffnung | H2 Ebene +1 | 1163Fen0813652937 | m² |  | Fensterarbeiten | Fensteröffnung |  | 3.75 |  | 1163Wa 0813652957 | AllplanAttributes - Positionsnummer_Text: U100
Türöffnung | H2 Ebene +1 | 1163Tür0813652945 | m² |  | Zimmer- und Holzbauarbeiten | Türöffnung |  | 3.75 | NEW | 1163Wa 0813652957 | REI 90-A1 | AllplanAttributes - Material: WA-STB; Tragendes Bauteil: yes; Brandabschnittsdefinierendes Bauteil: no; Außenliegend: yes; U-Wert: 0; Schallschutzklasse: 0; Codetext: Codetext; Türanschlag: -; Typ: 0; Brennbares Material: no; Brandverhalten: 0; Brandschutzklasse: A; Positionsnummer_Text: U100; Pset_OpeningElementCommon - Reference: Codetext
Fensteröffnung | H2 Ebene +1 | 1163Fen0813652943 | m² |  | Fensterarbeiten | Fensteröffnung |  | 3.75 |  | 1163Wa 0813652957 | AllplanAttributes - Positionsnummer_Text: U100
Wandnische | H2 Ebene +1 | 1163Wni0814491448 | m² | 0 | Zimmer- und Holzbauarbeiten | Wandnische | 0 |  | NEW
Türöffnung | H2 Ebene +1 | 1163Tür0812436829 | m² |  | Zimmer- und Holzbauarbeiten | Türöffnung |  | 3.75 | NEW | 1163Wa 0812437306 | AllplanAttributes - Codetext: Codetext; Türanschlag: DIN L; Attributset-Objekt: OpeningElement; Positionsnummer_Text: U100; Ortscode_Geschoßbezeichnung: E01; Pset_OpeningElementCommon - FireExit: no; Reference: Codetext
Türöffnung | H2 Ebene +1 | 1163Tür0812436834 | m² |  | Zimmer- und Holzbauarbeiten | Türöffnung |  | 3.75 | NEW | 1163Wa 0812437306 | EI2 30 | AllplanAttributes - Codetext: Codetext; Türanschlag: DIN L; Attributset-Objekt: OpeningElement; Rauchschutz: yes; Selbstschließend: yes; ash T_Zulage Schachttür: no; ash T_Dichtschließend: no; ash T_Feststellanlage (FSA): -; ash T_nicht abschließbar: no; Positionsnummer_Text: U100; Ortscode_Geschoßbezeichnung: E01; Pset_OpeningElementCommon - FireExit: no; Reference: Codetext
Wandnische | H2 Ebene +1 | 1163Wni0814781602 | m² | 0 | Zimmer- und Holzbauarbeiten | Wandnische | 0 |  | NEW
Wandnische | H2 Ebene +1 | 1163Wni0814594232 | m² | 0 | Zimmer- und Holzbauarbeiten | Wandnische | 0 |  | NEW
Wandnische | H2 Ebene +1 | 1163Wni0814491478 | m² | 0 | Zimmer- und Holzbauarbeiten | Wandnische | 0 |  | NEW
Deckendurchbruch | H2 Ebene +1 |  |  |  |  |  |  |  | NEW | Pset_OpeningElementCommon - FireExit: no; AllplanAttributes - Object Layer Attributes #1, Gewerk: Betonarbeiten; Object Layer Attributes #1, Allright_Bauteil_ID: 1164Ddu0000012691; Object Layer Attributes #1, Abrechnungsart: m²; Object Layer Attributes #1, Objektname: Bodendurchbruch; Object Layer Attributes #1, Attributset-Objekt: OpeningElement; Object Layer Attributes #1, Feuerwiderstandsklasse: 0; Object Layer Attributes #1, U-Wert: 0.9; Object Layer Attributes #1, Schallschutzklasse: 32; Object Layer Attributes #1, Sicherheitsklasse: -; Object Layer Attributes #1, Sonnenschutztyp: Movable; Object Layer Attributes #1, g-Wert: 0,51
Deckendurchbruch | H2 Ebene +1 |  |  |  |  |  |  |  | NEW | Pset_OpeningElementCommon - FireExit: no; AllplanAttributes - Object Layer Attributes #1, Gewerk: Betonarbeiten; Object Layer Attributes #1, Allright_Bauteil_ID: 1164Ddu0000012677; Object Layer Attributes #1, Abrechnungsart: m²; Object Layer Attributes #1, Objektname: Bodendurchbruch; Object Layer Attributes #1, Attributset-Objekt: OpeningElement; Object Layer Attributes #1, Feuerwiderstandsklasse: 0; Object Layer Attributes #1, U-Wert: 0.9; Object Layer Attributes #1, Schallschutzklasse: 32; Object Layer Attributes #1, Sicherheitsklasse: -; Object Layer Attributes #1, Sonnenschutztyp: Movable; Object Layer Attributes #1, g-Wert: 0,51
Deckendurchbruch | H2 Ebene +1 |  |  |  |  |  |  |  | NEW | Pset_OpeningElementCommon - FireExit: no; AllplanAttributes - Object Layer Attributes #1, Gewerk: Zimmer- und Holzbauarbeiten; Object Layer Attributes #1, Allright_Bauteil_ID: 1164Ddu0000004098; Object Layer Attributes #1, Abrechnungsart: m²; Object Layer Attributes #1, Objektname: Bodendurchbruch; Object Layer Attributes #1, Attributset-Objekt: OpeningElement; Object Layer Attributes #1, Feuerwiderstandsklasse: 0; Object Layer Attributes #1, U-Wert: 0.9; Object Layer Attributes #1, Schallschutzklasse: 32; Object Layer Attributes #1, Sicherheitsklasse: -; Object Layer Attributes #1, Sonnenschutztyp: Movable; Object Layer Attributes #1, g-Wert: 0,51
Deckendurchbruch | H2 Ebene +1 |  |  |  |  |  |  |  | NEW | Pset_OpeningElementCommon - FireExit: no; AllplanAttributes - Object Layer Attributes #1, Gewerk: Zimmer- und Holzbauarbeiten; Object Layer Attributes #1, Allright_Bauteil_ID: 1164Ddu0000004087; Object Layer Attributes #1, Abrechnungsart: m²; Object Layer Attributes #1, Objektname: Bodendurchbruch; Object Layer Attributes #1, Attributset-Objekt: OpeningElement; Object Layer Attributes #1, Feuerwiderstandsklasse: 0; Object Layer Attributes #1, U-Wert: 0.9; Object Layer Attributes #1, Schallschutzklasse: 32; Object Layer Attributes #1, Sicherheitsklasse: -; Object Layer Attributes #1, Sonnenschutztyp: Movable; Object Layer Attributes #1, g-Wert: 0,51
Deckendurchbruch | H2 Ebene +1 |  |  |  |  |  |  |  | NEW | Pset_OpeningElementCommon - FireExit: no; AllplanAttributes - Object Layer Attributes #1, Gewerk: Zimmer- und Holzbauarbeiten; Object Layer Attributes #1, Allright_Bauteil_ID: 1164Ddu0000004105; Object Layer Attributes #1, Abrechnungsart: m²; Object Layer Attributes #1, Objektname: Bodendurchbruch; Object Layer Attributes #1, Attributset-Objekt: OpeningElement; Object Layer Attributes #1, Feuerwiderstandsklasse: 0; Object Layer Attributes #1, U-Wert: 0.9; Object Layer Attributes #1, Schallschutzklasse: 32; Object Layer Attributes #1, Sicherheitsklasse: -; Object Layer Attributes #1, Sonnenschutztyp: Movable; Object Layer Attributes #1, g-Wert: 0,51
Deckendurchbruch | H2 Ebene +1 |  |  |  |  |  |  |  | NEW | Pset_OpeningElementCommon - FireExit: no; AllplanAttributes - Object Layer Attributes #1, Gewerk: Zimmer- und Holzbauarbeiten; Object Layer Attributes #1, Allright_Bauteil_ID: 1164Ddu0000004101; Object Layer Attributes #1, Abrechnungsart: m²; Object Layer Attributes #1, Objektname: Bodendurchbruch; Object Layer Attributes #1, Attributset-Objekt: OpeningElement; Object Layer Attributes #1, Feuerwiderstandsklasse: 0; Object Layer Attributes #1, U-Wert: 0.9; Object Layer Attributes #1, Schallschutzklasse: 32; Object Layer Attributes #1, Sicherheitsklasse: -; Object Layer Attributes #1, Sonnenschutztyp: Movable; Object Layer Attributes #1, g-Wert: 0,51
Deckendurchbruch | H2 Ebene +1 |  |  |  |  |  |  |  | NEW | Pset_OpeningElementCommon - FireExit: no; AllplanAttributes - Object Layer Attributes #1, Gewerk: Zimmer- und Holzbauarbeiten; Object Layer Attributes #1, Allright_Bauteil_ID: 1164Ddu0000004083; Object Layer Attributes #1, Abrechnungsart: m²; Object Layer Attributes #1, Objektname: Bodendurchbruch; Object Layer Attributes #1, Attributset-Objekt: OpeningElement; Object Layer Attributes #1, Feuerwiderstandsklasse: 0; Object Layer Attributes #1, U-Wert: 0.9; Object Layer Attributes #1, Schallschutzklasse: 32; Object Layer Attributes #1, Sicherheitsklasse: -; Object Layer Attributes #1, Sonnenschutztyp: Movable; Object Layer Attributes #1, g-Wert: 0,51
Deckendurchbruch | H2 Ebene +1 |  |  |  |  |  |  |  | NEW | Pset_OpeningElementCommon - FireExit: no; AllplanAttributes - Object Layer Attributes #1, Gewerk: Zimmer- und Holzbauarbeiten; Object Layer Attributes #1, Allright_Bauteil_ID: 1164Ddu0000007354; Object Layer Attributes #1, Abrechnungsart: m²; Object Layer Attributes #1, Objektname: Bodendurchbruch; Object Layer Attributes #1, Attributset-Objekt: OpeningElement; Object Layer Attributes #1, Feuerwiderstandsklasse: 0; Object Layer Attributes #1, U-Wert: 0.9; Object Layer Attributes #1, Schallschutzklasse: 32; Object Layer Attributes #1, Sicherheitsklasse: -; Object Layer Attributes #1, Sonnenschutztyp: Movable; Object Layer Attributes #1, g-Wert: 0,51
Deckendurchbruch | H2 Ebene +1 |  |  |  |  |  |  |  | NEW | Pset_OpeningElementCommon - FireExit: no; AllplanAttributes - Object Layer Attributes #1, Gewerk: Zimmer- und Holzbauarbeiten; Object Layer Attributes #1, Allright_Bauteil_ID: 1164Ddu0000007394; Object Layer Attributes #1, Abrechnungsart: m²; Object Layer Attributes #1, Objektname: Bodendurchbruch; Object Layer Attributes #1, Attributset-Objekt: OpeningElement; Object Layer Attributes #1, Feuerwiderstandsklasse: 0; Object Layer Attributes #1, U-Wert: 0.9; Object Layer Attributes #1, Schallschutzklasse: 32; Object Layer Attributes #1, Sicherheitsklasse: -; Object Layer Attributes #1, Sonnenschutztyp: Movable; Object Layer Attributes #1, g-Wert: 0,51
Deckendurchbruch | H2 Ebene +1 |  |  |  |  |  |  |  | NEW | Pset_OpeningElementCommon - FireExit: no; AllplanAttributes - Object Layer Attributes #1, Gewerk: Zimmer- und Holzbauarbeiten; Object Layer Attributes #1, Allright_Bauteil_ID: 1164Ddu0000004095; Object Layer Attributes #1, Abrechnungsart: m²; Object Layer Attributes #1, Objektname: Bodendurchbruch; Object Layer Attributes #1, Attributset-Objekt: OpeningElement; Object Layer Attributes #1, Feuerwiderstandsklasse: 0; Object Layer Attributes #1, U-Wert: 0.9; Object Layer Attributes #1, Schallschutzklasse: 32; Object Layer Attributes #1, Sicherheitsklasse: -; Object Layer Attributes #1, Sonnenschutztyp: Movable; Object Layer Attributes #1, g-Wert: 0,51
Deckendurchbruch | H2 Ebene +1 |  |  |  |  |  |  |  | NEW | Pset_OpeningElementCommon - FireExit: no; AllplanAttributes - Object Layer Attributes #1, Gewerk: Zimmer- und Holzbauarbeiten; Object Layer Attributes #1, Allright_Bauteil_ID: 1164Ddu0000004091; Object Layer Attributes #1, Abrechnungsart: m²; Object Layer Attributes #1, Objektname: Bodendurchbruch; Object Layer Attributes #1, Attributset-Objekt: OpeningElement; Object Layer Attributes #1, Feuerwiderstandsklasse: 0; Object Layer Attributes #1, U-Wert: 0.9; Object Layer Attributes #1, Schallschutzklasse: 32; Object Layer Attributes #1, Sicherheitsklasse: -; Object Layer Attributes #1, Sonnenschutztyp: Movable; Object Layer Attributes #1, g-Wert: 0,51
Deckendurchbruch | H2 Ebene +1 |  |  |  |  |  |  |  | NEW | Pset_OpeningElementCommon - FireExit: no; AllplanAttributes - Object Layer Attributes #1, Gewerk: Zimmer- und Holzbauarbeiten; Object Layer Attributes #1, Allright_Bauteil_ID: 1164Ddu0000004079; Object Layer Attributes #1, Abrechnungsart: m²; Object Layer Attributes #1, Objektname: Bodendurchbruch; Object Layer Attributes #1, Attributset-Objekt: OpeningElement; Object Layer Attributes #1, Feuerwiderstandsklasse: 0; Object Layer Attributes #1, U-Wert: 0.9; Object Layer Attributes #1, Schallschutzklasse: 32; Object Layer Attributes #1, Sicherheitsklasse: -; Object Layer Attributes #1, Sonnenschutztyp: Movable; Object Layer Attributes #1, g-Wert: 0,51
Türöffnung | H2 Ebene 0 | 1105Tür0000032897 | m² |  | Zimmer- und Holzbauarbeiten | Türöffnung |  | 0 | NEW | 1105Wa 0000062684 | 0 | RC 1 | 0,51 | AllplanAttributes - Türanschlag: DIN L; ash T_Feststellanlage (FSA): -; Positionsnummer_Text: U23
Türöffnung | H2 Ebene 0 | 1105Tür0000032898 | m³ | 0 | Zimmer- und Holzbauarbeiten | Türöffnung | 0 | 0 | NEW | 1105Wa 0000062683 | 0 | RC 1 | 0,51 | AllplanAttributes - Türanschlag: DIN L; ash T_Feststellanlage (FSA): -; Positionsnummer_Text: U23
Türöffnung | H2 Ebene 0 | 1105Tür0000032899 | m³ | 0 | Zimmer- und Holzbauarbeiten | Türöffnung | 0 | 0 | NEW | 1105Wa 0000062685 | 0 | RC 1 | 0,51 | AllplanAttributes - Türanschlag: DIN L; ash T_Feststellanlage (FSA): -; Positionsnummer_Text: U23
Türöffnung | H2 Ebene 0 | 1105Tür0000032900 | m² | 0 | Zimmer- und Holzbauarbeiten | Türöffnung | 0 | 0 | NEW | 1105Wa 0000062686 | 0 | RC 1 | 0,51 | AllplanAttributes - Türanschlag: DIN L; ash T_Feststellanlage (FSA): -; Positionsnummer_Text: U23
Türöffnung | H2 Ebene 0 | 1105Tür0000032901 | m² | 0 | Zimmer- und Holzbauarbeiten | Türöffnung | 0 | 0 | NEW | 1105Wa 0000062687 | 0 | RC 1 | 0,51 | AllplanAttributes - Türanschlag: DIN L; ash T_Feststellanlage (FSA): -; Positionsnummer_Text: U23
Türöffnung | H2 Ebene 0 | 1105Tür0000032902 | m² | 0 | Zimmer- und Holzbauarbeiten | Türöffnung | 0 | 0 | NEW | 1105Wa 0000062688 | 0 | RC 1 | 0,51 | AllplanAttributes - Türanschlag: DIN L; Positionsnummer_Text: U23
Türöffnung | H2 Ebene 0 | 1105Tür0811633407 | m² | 0 | Zimmer- und Holzbauarbeiten | Türöffnung | 0 |  | NEW | 1105Wa 0811633379 | AllplanAttributes - Türanschlag: DIN L; Positionsnummer_Text: U23
Fensteröffnung | H2 Ebene 0 | 1105Fen0000061495 | m² |  | Fensterarbeiten | Fensteröffnung |  | 0 |  | 1105Wa 0000002907 | 0 | RC 1 | 0,51 | AllplanAttributes - Positionsnummer_Text: U23
Fensteröffnung | H2 Ebene 0 | 1105Fen0000061493 | m³ | 0 | Fensterarbeiten | Fensteröffnung | 0 | 0 |  | 1105Wa 0000002903 | 0 | RC 1 | 0,51 | AllplanAttributes - Positionsnummer_Text: U23
Fensteröffnung | H2 Ebene 0 | 1105Fen0000061491 | m³ | 0 | Fensterarbeiten | Fensteröffnung | 0 | 0 |  | 1105Wa 0000002899 | 0 | RC 1 | 0,51 | AllplanAttributes - Positionsnummer_Text: U23
Fensteröffnung | H2 Ebene 0 | 1105Fen0000061489 | m² | 0 | Fensterarbeiten | Fensteröffnung | 0 | 0 |  | 1105Wa 0000002895 | 0 | RC 1 | 0,51 | AllplanAttributes - Positionsnummer_Text: U23
Fensteröffnung | H2 Ebene 0 | 1105Fen0000061487 | m² | 0 | Fensterarbeiten | Fensteröffnung | 0 | 0 | NEW | 1105Wa 0000002891 | 0 | RC 1 | 0,51 | AllplanAttributes - Positionsnummer_Text: U23
Fensteröffnung | H2 Ebene 0 | 1105Fen0000061485 | m² | 0 | Fensterarbeiten | Fensteröffnung | 0 | 0 | NEW | 1105Wa 0000002887 | 0 | RC 1 | 0,51 | AllplanAttributes - Positionsnummer_Text: U23
Fensteröffnung | H2 Ebene 0 | 1105Fen0000061483 | m² | 0 | Fensterarbeiten | Fensteröffnung | 0 | 0 | NEW | 1105Wa 0000002883 | 0 | RC 1 | 0,51 | AllplanAttributes - Positionsnummer_Text: U23
Fensteröffnung | H2 Ebene 0 | 1105Fen0000040999 | m² |  | Wärmedämm-Verbundsysteme | Fensteröffnung |  | 0 | NEW | 1105Wa 0000000388 | 0 | RC 1 | 0,51 | AllplanAttributes - Material: Fensterelement; Tragendes Bauteil: no; Brandabschnittsdefinierendes Bauteil: no; Positionsnummer_Text: U23
Fensteröffnung | H2 Ebene 0 | 1105Fen0000041167 | m² |  | Wärmedämm-Verbundsysteme | Fensteröffnung |  | 0 | NEW | 1105Wa 0000000388 | 0 | RC 1 | 0,51 | AllplanAttributes - Material: Fensterelement; Tragendes Bauteil: no; Brandabschnittsdefinierendes Bauteil: no; ash D_Detailverweis: Typ 1; ash D_Plannummer: D1726; Positionsnummer_Text: U23
Fensteröffnung | H2 Ebene 0 | 1105Fen0000041000 | m³ | 0 | Wärmedämm-Verbundsysteme | Fensteröffnung | 0 | 0 | NEW | 1105Wa 0000000384 | 0 | RC 1 | 0,51 | AllplanAttributes - Material: Fensterelement; Außenliegend: yes; Positionsnummer_Text: U23
Fensteröffnung | H2 Ebene 0 | 1105Fen0000041168 | m³ | 0 | Wärmedämm-Verbundsysteme | Fensteröffnung | 0 | 0 | NEW | 1105Wa 0000000384 | 0 | RC 1 | 0,51 | AllplanAttributes - Material: Fensterelement; Außenliegend: yes; ash D_Detailverweis: Typ 1; ash D_Plannummer: D1726; Positionsnummer_Text: U23
Fensteröffnung | H2 Ebene 0 | 1105Fen0000041001 | m³ | 0 | Wärmedämm-Verbundsysteme | Fensteröffnung | 0 | 0 | NEW | 1105Wa 0000000364 | 0 | RC 1 | 0,51 | AllplanAttributes - Positionsnummer_Text: U23
Fensteröffnung | H2 Ebene 0 | 1105Fen0000041169 | m³ | 0 | Wärmedämm-Verbundsysteme | Fensteröffnung | 0 | 0 | NEW | 1105Wa 0000000364 | 0 | RC 1 | 0,51 | AllplanAttributes - ash D_Detailverweis: Typ 1; ash D_Plannummer: D1726; Positionsnummer_Text: U23
Fensteröffnung | H2 Ebene 0 | 1105Fen0000041002 | m² | 0 | Wärmedämm-Verbundsysteme | Fensteröffnung | 0 | 0 | NEW | 1105Wa 0000000368 | 0 | RC 1 | 0,51 | AllplanAttributes - Positionsnummer_Text: U23
Fensteröffnung | H2 Ebene 0 | 1105Fen0000041170 | m² | 0 | Wärmedämm-Verbundsysteme | Fensteröffnung | 0 | 0 | NEW | 1105Wa 0000000368 | 0 | RC 1 | 0,51 | AllplanAttributes - ash D_Detailverweis: Typ 1; ash D_Plannummer: D1726; Positionsnummer_Text: U23
Fensteröffnung | H2 Ebene 0 | 1105Fen0000041003 | m² | 0 | Wärmedämm-Verbundsysteme | Fensteröffnung | 0 | 0 | NEW | 1105Wa 0000000372 | 0 | RC 1 | 0,51 | AllplanAttributes - Positionsnummer_Text: U23
Fensteröffnung | H2 Ebene 0 | 1105Fen0000041171 | m² | 0 | Wärmedämm-Verbundsysteme | Fensteröffnung | 0 | 0 | NEW | 1105Wa 0000000372 | 0 | RC 1 | 0,51 | AllplanAttributes - ash D_Detailverweis: Typ 1; ash D_Plannummer: D1726; Positionsnummer_Text: U23
Fensteröffnung | H2 Ebene 0 | 1105Fen0000041004 | m² | 0 | Wärmedämm-Verbundsysteme | Fensteröffnung | 0 | 0 | NEW | 1105Wa 0000000376 | 0 | RC 1 | 0,51 | AllplanAttributes - Positionsnummer_Text: U23
Fensteröffnung | H2 Ebene 0 | 1105Fen0000041172 | m² | 0 | Wärmedämm-Verbundsysteme | Fensteröffnung | 0 | 0 | NEW | 1105Wa 0000000376 | 0 | RC 1 | 0,51 | AllplanAttributes - ash D_Detailverweis: Typ 1; ash D_Plannummer: D1726; Positionsnummer_Text: U23
Fensteröffnung | H2 Ebene 0 | 1105Fen0000041005 | m² | 0 | Wärmedämm-Verbundsysteme | Fensteröffnung | 0 | 0 | NEW | 1105Wa 0000000380 | 0 | RC 1 | 0,51 | AllplanAttributes - Positionsnummer_Text: U23
Fensteröffnung | H2 Ebene 0 | 1105Fen0000041173 | m² | 0 | Wärmedämm-Verbundsysteme | Fensteröffnung | 0 | 0 | NEW | 1105Wa 0000000380 | 0 | RC 1 | 0,51 | AllplanAttributes - ash D_Detailverweis: Typ 1; ash D_Plannummer: D1726; Positionsnummer_Text: U23
Fensteröffnung | H2 Ebene 0 | 1105Fen0000043704 | m² |  | Wärmedämm-Verbundsysteme | Fensteröffnung |  | 0 | NEW | 1105Wa 0000001159 | 0 | RC 1 | 0,51 | AllplanAttributes - Material: Fensterelement; Tragendes Bauteil: no; Brandabschnittsdefinierendes Bauteil: no; Positionsnummer_Text: U23
Fensteröffnung | H2 Ebene 0 | 1105Fen0000043830 | m² |  | Wärmedämm-Verbundsysteme | Fensteröffnung |  | 0 | NEW | 1105Wa 0000001159 | 0 | RC 1 | 0,51 | AllplanAttributes - Material: Fensterelement; Tragendes Bauteil: no; Brandabschnittsdefinierendes Bauteil: no; Positionsnummer_Text: U23
Fensteröffnung | H2 Ebene 0 | 1105Fen0000043831 | m³ | 0 | Wärmedämm-Verbundsysteme | Fensteröffnung | 0 | 0 | NEW | 1105Wa 0000001155 | 0 | RC 1 | 0,51 | AllplanAttributes - Material: Fensterelement; Außenliegend: yes; Positionsnummer_Text: U23
Fensteröffnung | H2 Ebene 0 | 1105Fen0000043705 | m³ | 0 | Wärmedämm-Verbundsysteme | Fensteröffnung | 0 | 0 | NEW | 1105Wa 0000001155 | 0 | RC 1 | 0,51 | AllplanAttributes - Material: Fensterelement; Außenliegend: yes; Positionsnummer_Text: U23
Fensteröffnung | H2 Ebene 0 | 1105Fen0000043706 | m³ | 0 | Wärmedämm-Verbundsysteme | Fensteröffnung | 0 | 0 | NEW | 1105Wa 0000001135 | 0 | RC 1 | 0,51 | AllplanAttributes - Positionsnummer_Text: U23
Fensteröffnung | H2 Ebene 0 | 1105Fen0000043832 | m³ | 0 | Wärmedämm-Verbundsysteme | Fensteröffnung | 0 | 0 | NEW | 1105Wa 0000001135 | 0 | RC 1 | 0,51 | AllplanAttributes - Positionsnummer_Text: U23
Fensteröffnung | H2 Ebene 0 | 1105Fen0000043707 | m² | 0 | Wärmedämm-Verbundsysteme | Fensteröffnung | 0 | 0 | NEW | 1105Wa 0000001139 | 0 | RC 1 | 0,51 | AllplanAttributes - Positionsnummer_Text: U23
Fensteröffnung | H2 Ebene 0 | 1105Fen0000043833 | m² | 0 | Wärmedämm-Verbundsysteme | Fensteröffnung | 0 | 0 | NEW | 1105Wa 0000001139 | 0 | RC 1 | 0,51 | AllplanAttributes - Positionsnummer_Text: U23
Fensteröffnung | H2 Ebene 0 | 1105Fen0000043708 | m² | 0 | Wärmedämm-Verbundsysteme | Fensteröffnung | 0 | 0 | NEW | 1105Wa 0000001143 | 0 | RC 1 | 0,51 | AllplanAttributes - Positionsnummer_Text: U23
Fensteröffnung | H2 Ebene 0 | 1105Fen0000043834 | m² | 0 | Wärmedämm-Verbundsysteme | Fensteröffnung | 0 | 0 | NEW | 1105Wa 0000001143 | 0 | RC 1 | 0,51 | AllplanAttributes - Positionsnummer_Text: U23
Fensteröffnung | H2 Ebene 0 | 1105Fen0000043709 | m² | 0 | Wärmedämm-Verbundsysteme | Fensteröffnung | 0 | 0 | NEW | 1105Wa 0000001147 | 0 | RC 1 | 0,51 | AllplanAttributes - Positionsnummer_Text: U23
Fensteröffnung | H2 Ebene 0 | 1105Fen0000043835 | m² | 0 | Wärmedämm-Verbundsysteme | Fensteröffnung | 0 | 0 | NEW | 1105Wa 0000001147 | 0 | RC 1 | 0,51 | AllplanAttributes - Positionsnummer_Text: U23
Fensteröffnung | H2 Ebene 0 | 1105Fen0000043836 | m² | 0 | Wärmedämm-Verbundsysteme | Fensteröffnung | 0 | 0 | NEW | 1105Wa 0000001151 | 0 | RC 1 | 0,51 | AllplanAttributes - Positionsnummer_Text: U23
Fensteröffnung | H2 Ebene 0 | 1105Fen0000043710 | m² | 0 | Wärmedämm-Verbundsysteme | Fensteröffnung | 0 | 0 | NEW | 1105Wa 0000001151 | 0 | RC 1 | 0,51 | AllplanAttributes - Positionsnummer_Text: U23
Fensteröffnung | H2 Ebene 0 | 1105Fen0000057069 | m² | 0 | Fensterarbeiten | Fensteröffnung | 0 | 0 |  | 1105Wa 0000005133 | 0 | RC 1 | 0,51 | AllplanAttributes - Positionsnummer_Text: U23
Fensteröffnung | H2 Ebene 0 | 1105Fen0000057111 | m² | 0 | Fensterarbeiten | Fensteröffnung | 0 | 0 |  | 1105Wa 0000005133 | 0 | RC 1 | 0,51 | AllplanAttributes - Positionsnummer_Text: U23
Fensteröffnung | H2 Ebene 0 | 1105Fen0000057153 | m² | 0 | Fensterarbeiten | Fensteröffnung | 0 | 0 |  | 1105Wa 0000005133 | 0 | RC 1 | 0,51 | AllplanAttributes - Positionsnummer_Text: U23
Fensteröffnung | H2 Ebene 0 | 1105Fen0000057237 | m² | 0 | Fensterarbeiten | Fensteröffnung | 0 | 0 |  | 1105Wa 0000005133 | 0 | RC 1 | 0,51 | AllplanAttributes - Positionsnummer_Text: U23
Fensteröffnung | H2 Ebene 0 | 1105Fen0000085787 | m² | 0 | Fensterarbeiten | Fensteröffnung | 0 | 0 |  | 1105Wa 0000005133 | 0 | RC 1 | 0,51 | AllplanAttributes - Positionsnummer_Text: U23
Fensteröffnung | H2 Ebene 0 | 1105Fen0000057195 | m² | 0 | Fensterarbeiten | Fensteröffnung | 0 | 0 |  | 1105Wa 0000005133 | 0 | RC 1 | 0,51 | AllplanAttributes - Positionsnummer_Text: U23
Fensteröffnung | H2 Ebene 0 | 1105Fen0000057068 | m³ | 0 | Fensterarbeiten | Fensteröffnung | 0 | 0 |  | 1105Wa 0000005124 | 0 | RC 1 | 0,51 | AllplanAttributes - Positionsnummer_Text: U23
Fensteröffnung | H2 Ebene 0 | 1105Fen0000057110 | m³ | 0 | Fensterarbeiten | Fensteröffnung | 0 | 0 |  | 1105Wa 0000005124 | 0 | RC 1 | 0,51 | AllplanAttributes - Positionsnummer_Text: U23
Fensteröffnung | H2 Ebene 0 | 1105Fen0000057152 | m³ | 0 | Fensterarbeiten | Fensteröffnung | 0 | 0 |  | 1105Wa 0000005124 | 0 | RC 1 | 0,51 | AllplanAttributes - Positionsnummer_Text: U23
Fensteröffnung | H2 Ebene 0 | 1105Fen0000057236 | m³ | 0 | Fensterarbeiten | Fensteröffnung | 0 | 0 |  | 1105Wa 0000005124 | 0 | RC 1 | 0,51 | AllplanAttributes - Positionsnummer_Text: U23
Fensteröffnung | H2 Ebene 0 | 1105Fen0000085771 | m³ | 0 | Fensterarbeiten | Fensteröffnung | 0 | 0 |  | 1105Wa 0000005124 | 0 | RC 1 | 0,51 | AllplanAttributes - Positionsnummer_Text: U23
Fensteröffnung | H2 Ebene 0 | 1105Fen0000057194 | m³ | 0 | Fensterarbeiten | Fensteröffnung | 0 | 0 |  | 1105Wa 0000005124 | 0 | RC 1 | 0,51 | AllplanAttributes - Positionsnummer_Text: U23
Fensteröffnung | H2 Ebene 0 | 1105Fen0000057067 | m³ | 0 | Fensterarbeiten | Fensteröffnung | 0 | 0 |  | 1105Wa 0000005115 | 0 | RC 1 | 0,51 | AllplanAttributes - Positionsnummer_Text: U23
Fensteröffnung | H2 Ebene 0 | 1105Fen0000057109 | m³ | 0 | Fensterarbeiten | Fensteröffnung | 0 | 0 |  | 1105Wa 0000005115 | 0 | RC 1 | 0,51 | AllplanAttributes - Positionsnummer_Text: U23
Fensteröffnung | H2 Ebene 0 | 1105Fen0000057151 | m³ | 0 | Fensterarbeiten | Fensteröffnung | 0 | 0 |  | 1105Wa 0000005115 | 0 | RC 1 | 0,51 | AllplanAttributes - Positionsnummer_Text: U23
Fensteröffnung | H2 Ebene 0 | 1105Fen0000057235 | m³ | 0 | Fensterarbeiten | Fensteröffnung | 0 | 0 |  | 1105Wa 0000005115 | 0 | RC 1 | 0,51 | AllplanAttributes - Positionsnummer_Text: U23
Fensteröffnung | H2 Ebene 0 | 1105Fen0000085769 | m³ | 0 | Fensterarbeiten | Fensteröffnung | 0 | 0 |  | 1105Wa 0000005115 | 0 | RC 1 | 0,51 | AllplanAttributes - Positionsnummer_Text: U23
Fensteröffnung | H2 Ebene 0 | 1105Fen0000057193 | m³ | 0 | Fensterarbeiten | Fensteröffnung | 0 | 0 |  | 1105Wa 0000005115 | 0 | RC 1 | 0,51 | AllplanAttributes - Positionsnummer_Text: U23
Fensteröffnung | H2 Ebene 0 | 1105Fen0000057066 | m² | 0 | Fensterarbeiten | Fensteröffnung | 0 | 0 |  | 1105Wa 0000005106 | 0 | RC 1 | 0,51 | AllplanAttributes - Positionsnummer_Text: U23
Fensteröffnung | H2 Ebene 0 | 1105Fen0000057108 | m² | 0 | Fensterarbeiten | Fensteröffnung | 0 | 0 |  | 1105Wa 0000005106 | 0 | RC 1 | 0,51 | AllplanAttributes - Positionsnummer_Text: U23
Fensteröffnung | H2 Ebene 0 | 1105Fen0000057150 | m² | 0 | Fensterarbeiten | Fensteröffnung | 0 | 0 |  | 1105Wa 0000005106 | 0 | RC 1 | 0,51 | AllplanAttributes - Positionsnummer_Text: U23
Fensteröffnung | H2 Ebene 0 | 1105Fen0000057234 | m² | 0 | Fensterarbeiten | Fensteröffnung | 0 | 0 |  | 1105Wa 0000005106 | 0 | RC 1 | 0,51 | AllplanAttributes - Positionsnummer_Text: U23
Fensteröffnung | H2 Ebene 0 | 1105Fen0000085767 | m² | 0 | Fensterarbeiten | Fensteröffnung | 0 | 0 |  | 1105Wa 0000005106 | 0 | RC 1 | 0,51 | AllplanAttributes - Positionsnummer_Text: U23
Fensteröffnung | H2 Ebene 0 | 1105Fen0000057192 | m² | 0 | Fensterarbeiten | Fensteröffnung | 0 | 0 |  | 1105Wa 0000005106 | 0 | RC 1 | 0,51 | AllplanAttributes - Positionsnummer_Text: U23
Fensteröffnung | H2 Ebene 0 | 1105Fen0000057065 | m² | 0 | Fensterarbeiten | Fensteröffnung | 0 | 0 | NEW | 1105Wa 0000005097 | 0 | RC 1 | 0,51 | AllplanAttributes - Positionsnummer_Text: U23
Fensteröffnung | H2 Ebene 0 | 1105Fen0000057107 | m² | 0 | Fensterarbeiten | Fensteröffnung | 0 | 0 | NEW | 1105Wa 0000005097 | 0 | RC 1 | 0,51 | AllplanAttributes - Positionsnummer_Text: U23
Fensteröffnung | H2 Ebene 0 | 1105Fen0000057149 | m² | 0 | Fensterarbeiten | Fensteröffnung | 0 | 0 | NEW | 1105Wa 0000005097 | 0 | RC 1 | 0,51 | AllplanAttributes - Positionsnummer_Text: U23
Fensteröffnung | H2 Ebene 0 | 1105Fen0000057233 | m² | 0 | Fensterarbeiten | Fensteröffnung | 0 | 0 | NEW | 1105Wa 0000005097 | 0 | RC 1 | 0,51 | AllplanAttributes - Positionsnummer_Text: U23
Fensteröffnung | H2 Ebene 0 | 1105Fen0000085765 | m² | 0 | Fensterarbeiten | Fensteröffnung | 0 | 0 | NEW | 1105Wa 0000005097 | 0 | RC 1 | 0,51 | AllplanAttributes - Positionsnummer_Text: U23
Fensteröffnung | H2 Ebene 0 | 1105Fen0000057191 | m² | 0 | Fensterarbeiten | Fensteröffnung | 0 | 0 | NEW | 1105Wa 0000005097 | 0 | RC 1 | 0,51 | AllplanAttributes - Positionsnummer_Text: U23
Fensteröffnung | H2 Ebene 0 | 1105Fen0000057064 | m² | 0 | Fensterarbeiten | Fensteröffnung | 0 | 0 | NEW | 1105Wa 0000005088 | 0 | RC 1 | 0,51 | AllplanAttributes - Positionsnummer_Text: U23
Fensteröffnung | H2 Ebene 0 | 1105Fen0000057106 | m² | 0 | Fensterarbeiten | Fensteröffnung | 0 | 0 | NEW | 1105Wa 0000005088 | 0 | RC 1 | 0,51 | AllplanAttributes - Positionsnummer_Text: U23
Fensteröffnung | H2 Ebene 0 | 1105Fen0000057148 | m² | 0 | Fensterarbeiten | Fensteröffnung | 0 | 0 | NEW | 1105Wa 0000005088 | 0 | RC 1 | 0,51 | AllplanAttributes - Positionsnummer_Text: U23
Fensteröffnung | H2 Ebene 0 | 1105Fen0000057232 | m² | 0 | Fensterarbeiten | Fensteröffnung | 0 | 0 | NEW | 1105Wa 0000005088 | 0 | RC 1 | 0,51 | AllplanAttributes - Positionsnummer_Text: U23
Fensteröffnung | H2 Ebene 0 | 1105Fen0000085763 | m² | 0 | Fensterarbeiten | Fensteröffnung | 0 | 0 | NEW | 1105Wa 0000005088 | 0 | RC 1 | 0,51 | AllplanAttributes - Positionsnummer_Text: U23
Fensteröffnung | H2 Ebene 0 | 1105Fen0000057190 | m² | 0 | Fensterarbeiten | Fensteröffnung | 0 | 0 | NEW | 1105Wa 0000005088 | 0 | RC 1 | 0,51 | AllplanAttributes - Positionsnummer_Text: U23
Fensteröffnung | H2 Ebene 0 | 1105Fen0000057063 | m² | 0 | Fensterarbeiten | Fensteröffnung | 0 | 0 | NEW | 1105Wa 0000005079 | 0 | RC 1 | 0,51 | AllplanAttributes - Positionsnummer_Text: U23
Fensteröffnung | H2 Ebene 0 | 1105Fen0000057105 | m² | 0 | Fensterarbeiten | Fensteröffnung | 0 | 0 | NEW | 1105Wa 0000005079 | 0 | RC 1 | 0,51 | AllplanAttributes - Positionsnummer_Text: U23
Fensteröffnung | H2 Ebene 0 | 1105Fen0000057147 | m² | 0 | Fensterarbeiten | Fensteröffnung | 0 | 0 | NEW | 1105Wa 0000005079 | 0 | RC 1 | 0,51 | AllplanAttributes - Positionsnummer_Text: U23
Fensteröffnung | H2 Ebene 0 | 1105Fen0000057231 | m² | 0 | Fensterarbeiten | Fensteröffnung | 0 | 0 | NEW | 1105Wa 0000005079 | 0 | RC 1 | 0,51 | AllplanAttributes - Positionsnummer_Text: U23
Fensteröffnung | H2 Ebene 0 | 1105Fen0000085761 | m² | 0 | Fensterarbeiten | Fensteröffnung | 0 | 0 | NEW | 1105Wa 0000005079 | 0 | RC 1 | 0,51 | AllplanAttributes - Positionsnummer_Text: U23
Fensteröffnung | H2 Ebene 0 | 1105Fen0000057189 | m² | 0 | Fensterarbeiten | Fensteröffnung | 0 | 0 | NEW | 1105Wa 0000005079 | 0 | RC 1 | 0,51 | AllplanAttributes - Positionsnummer_Text: U23
Fensteröffnung | H2 Ebene 0 | 1105Fen2005792971 | m² | 0 | Fensterarbeiten | Fensteröffnung | 0 | 0 |  | 1105Wa 0000005133 | 0 | RC 1 | 0,51 | AllplanAttributes - Positionsnummer_Text: U23
Fensteröffnung | H2 Ebene 0 | 1105Fen2005793085 | m² | 0 | Fensterarbeiten | Fensteröffnung | 0 | 0 |  | 1105Wa 0000005133 | 0 | RC 1 | 0,51 | AllplanAttributes - Positionsnummer_Text: U23
Fensteröffnung | H2 Ebene 0 | 1105Fen2005793167 | m² | 0 | Fensterarbeiten | Fensteröffnung | 0 | 0 |  | 1105Wa 0000005133 | 0 | RC 1 | 0,51 | AllplanAttributes - Positionsnummer_Text: U23
Fensteröffnung | H2 Ebene 0 | 1105Fen2005793261 | m² | 0 | Fensterarbeiten | Fensteröffnung | 0 | 0 |  | 1105Wa 0000005133 | 0 | RC 1 | 0,51 | AllplanAttributes - Positionsnummer_Text: U23
Fensteröffnung | H2 Ebene 0 | 1105Fen2005793343 | m² | 0 | Fensterarbeiten | Fensteröffnung | 0 | 0 |  | 1105Wa 0000005133 | 0 | RC 1 | 0,51 | AllplanAttributes - Positionsnummer_Text: U23
Fensteröffnung | H2 Ebene 0 | 1105Fen2005792970 | m³ | 0 | Fensterarbeiten | Fensteröffnung | 0 | 0 |  | 1105Wa 0000005124 | 0 | RC 1 | 0,51 | AllplanAttributes - Positionsnummer_Text: U23
Fensteröffnung | H2 Ebene 0 | 1105Fen2005793084 | m³ | 0 | Fensterarbeiten | Fensteröffnung | 0 | 0 |  | 1105Wa 0000005124 | 0 | RC 1 | 0,51 | AllplanAttributes - Positionsnummer_Text: U23
Fensteröffnung | H2 Ebene 0 | 1105Fen2005793166 | m³ | 0 | Fensterarbeiten | Fensteröffnung | 0 | 0 |  | 1105Wa 0000005124 | 0 | RC 1 | 0,51 | AllplanAttributes - Positionsnummer_Text: U23
Fensteröffnung | H2 Ebene 0 | 1105Fen2005793260 | m³ | 0 | Fensterarbeiten | Fensteröffnung | 0 | 0 |  | 1105Wa 0000005124 | 0 | RC 1 | 0,51 | AllplanAttributes - Positionsnummer_Text: U23
Fensteröffnung | H2 Ebene 0 | 1105Fen2005793342 | m³ | 0 | Fensterarbeiten | Fensteröffnung | 0 | 0 |  | 1105Wa 0000005124 | 0 | RC 1 | 0,51 | AllplanAttributes - Positionsnummer_Text: U23
Fensteröffnung | H2 Ebene 0 | 1105Fen2005792969 | m³ | 0 | Fensterarbeiten | Fensteröffnung | 0 | 0 |  | 1105Wa 0000005115 | 0 | RC 1 | 0,51 | AllplanAttributes - Positionsnummer_Text: U23
Fensteröffnung | H2 Ebene 0 | 1105Fen2005793083 | m³ | 0 | Fensterarbeiten | Fensteröffnung | 0 | 0 |  | 1105Wa 0000005115 | 0 | RC 1 | 0,51 | AllplanAttributes - Positionsnummer_Text: U23
Fensteröffnung | H2 Ebene 0 | 1105Fen2005793165 | m³ | 0 | Fensterarbeiten | Fensteröffnung | 0 | 0 |  | 1105Wa 0000005115 | 0 | RC 1 | 0,51 | AllplanAttributes - Positionsnummer_Text: U23
Fensteröffnung | H2 Ebene 0 | 1105Fen2005793259 | m³ | 0 | Fensterarbeiten | Fensteröffnung | 0 | 0 |  | 1105Wa 0000005115 | 0 | RC 1 | 0,51 | AllplanAttributes - Positionsnummer_Text: U23
Fensteröffnung | H2 Ebene 0 | 1105Fen2005793341 | m³ | 0 | Fensterarbeiten | Fensteröffnung | 0 | 0 |  | 1105Wa 0000005115 | 0 | RC 1 | 0,51 | AllplanAttributes - Positionsnummer_Text: U23
Fensteröffnung | H2 Ebene 0 | 1105Fen2005792968 | m² | 0 | Fensterarbeiten | Fensteröffnung | 0 | 0 |  | 1105Wa 0000005106 | 0 | RC 1 | 0,51 | AllplanAttributes - Positionsnummer_Text: U23
Fensteröffnung | H2 Ebene 0 | 1105Fen2005793082 | m² | 0 | Fensterarbeiten | Fensteröffnung | 0 | 0 |  | 1105Wa 0000005106 | 0 | RC 1 | 0,51 | AllplanAttributes - Positionsnummer_Text: U23
Fensteröffnung | H2 Ebene 0 | 1105Fen2005793164 | m² | 0 | Fensterarbeiten | Fensteröffnung | 0 | 0 |  | 1105Wa 0000005106 | 0 | RC 1 | 0,51 | AllplanAttributes - Positionsnummer_Text: U23
Fensteröffnung | H2 Ebene 0 | 1105Fen2005793258 | m² | 0 | Fensterarbeiten | Fensteröffnung | 0 | 0 |  | 1105Wa 0000005106 | 0 | RC 1 | 0,51 | AllplanAttributes - Positionsnummer_Text: U23
Fensteröffnung | H2 Ebene 0 | 1105Fen2005793340 | m² | 0 | Fensterarbeiten | Fensteröffnung | 0 | 0 |  | 1105Wa 0000005106 | 0 | RC 1 | 0,51 | AllplanAttributes - Positionsnummer_Text: U23
Fensteröffnung | H2 Ebene 0 | 1105Fen2005792967 | m² | 0 | Fensterarbeiten | Fensteröffnung | 0 | 0 | NEW | 1105Wa 0000005097 | 0 | RC 1 | 0,51 | AllplanAttributes - Positionsnummer_Text: U23
Fensteröffnung | H2 Ebene 0 | 1105Fen2005793081 | m² | 0 | Fensterarbeiten | Fensteröffnung | 0 | 0 | NEW | 1105Wa 0000005097 | 0 | RC 1 | 0,51 | AllplanAttributes - Positionsnummer_Text: U23
Fensteröffnung | H2 Ebene 0 | 1105Fen2005793163 | m² | 0 | Fensterarbeiten | Fensteröffnung | 0 | 0 | NEW | 1105Wa 0000005097 | 0 | RC 1 | 0,51 | AllplanAttributes - Positionsnummer_Text: U23
Fensteröffnung | H2 Ebene 0 | 1105Fen2005793257 | m² | 0 | Fensterarbeiten | Fensteröffnung | 0 | 0 | NEW | 1105Wa 0000005097 | 0 | RC 1 | 0,51 | AllplanAttributes - Positionsnummer_Text: U23
Fensteröffnung | H2 Ebene 0 | 1105Fen2005793339 | m² | 0 | Fensterarbeiten | Fensteröffnung | 0 | 0 | NEW | 1105Wa 0000005097 | 0 | RC 1 | 0,51 | AllplanAttributes - Positionsnummer_Text: U23
Fensteröffnung | H2 Ebene 0 | 1105Fen2005792966 | m² | 0 | Fensterarbeiten | Fensteröffnung | 0 | 0 | NEW | 1105Wa 0000005088 | 0 | RC 1 | 0,51 | AllplanAttributes - Positionsnummer_Text: U23
Fensteröffnung | H2 Ebene 0 | 1105Fen2005793080 | m² | 0 | Fensterarbeiten | Fensteröffnung | 0 | 0 | NEW | 1105Wa 0000005088 | 0 | RC 1 | 0,51 | AllplanAttributes - Positionsnummer_Text: U23
Fensteröffnung | H2 Ebene 0 | 1105Fen2005793162 | m² | 0 | Fensterarbeiten | Fensteröffnung | 0 | 0 | NEW | 1105Wa 0000005088 | 0 | RC 1 | 0,51 | AllplanAttributes - Positionsnummer_Text: U23
Fensteröffnung | H2 Ebene 0 | 1105Fen2005793256 | m² | 0 | Fensterarbeiten | Fensteröffnung | 0 | 0 | NEW | 1105Wa 0000005088 | 0 | RC 1 | 0,51 | AllplanAttributes - Positionsnummer_Text: U23
Fensteröffnung | H2 Ebene 0 | 1105Fen2005793338 | m² | 0 | Fensterarbeiten | Fensteröffnung | 0 | 0 | NEW | 1105Wa 0000005088 | 0 | RC 1 | 0,51 | AllplanAttributes - Positionsnummer_Text: U23
Fensteröffnung | H2 Ebene 0 | 1105Fen2005792965 | m² | 0 | Fensterarbeiten | Fensteröffnung | 0 | 0 | NEW | 1105Wa 0000005079 | 0 | RC 1 | 0,51 | AllplanAttributes - Positionsnummer_Text: U23
Fensteröffnung | H2 Ebene 0 | 1105Fen2005793079 | m² | 0 | Fensterarbeiten | Fensteröffnung | 0 | 0 | NEW | 1105Wa 0000005079 | 0 | RC 1 | 0,51 | AllplanAttributes - Positionsnummer_Text: U23
Fensteröffnung | H2 Ebene 0 | 1105Fen2005793161 | m² | 0 | Fensterarbeiten | Fensteröffnung | 0 | 0 | NEW | 1105Wa 0000005079 | 0 | RC 1 | 0,51 | AllplanAttributes - Positionsnummer_Text: U23
Fensteröffnung | H2 Ebene 0 | 1105Fen2005793255 | m² | 0 | Fensterarbeiten | Fensteröffnung | 0 | 0 | NEW | 1105Wa 0000005079 | 0 | RC 1 | 0,51 | AllplanAttributes - Positionsnummer_Text: U23
Fensteröffnung | H2 Ebene 0 | 1105Fen2005793337 | m² | 0 | Fensterarbeiten | Fensteröffnung | 0 | 0 | NEW | 1105Wa 0000005079 | 0 | RC 1 | 0,51 | AllplanAttributes - Positionsnummer_Text: U23
Fensteröffnung | H2 Ebene 0 | 1105Fen0000053604 | m² |  | Fensterarbeiten | Fensteröffnung |  | 0 |  | 1105Wa 0000004611 | 0 | RC 1 | 0,51 | AllplanAttributes - Positionsnummer_Text: U23
Fensteröffnung | H2 Ebene 0 | 1105Fen0000053605 | m³ | 0 | Fensterarbeiten | Fensteröffnung | 0 | 0 |  | 1105Wa 0000004607 | 0 | RC 1 | 0,51 | AllplanAttributes - Positionsnummer_Text: U23
Fensteröffnung | H2 Ebene 0 | 1105Fen0000053606 | m³ | 0 | Fensterarbeiten | Fensteröffnung | 0 | 0 |  | 1105Wa 0000004603 | 0 | RC 1 | 0,51 | AllplanAttributes - Positionsnummer_Text: U23
Fensteröffnung | H2 Ebene 0 | 1105Fen0000053607 | m² | 0 | Fensterarbeiten | Fensteröffnung | 0 | 0 |  | 1105Wa 0000004599 | 0 | RC 1 | 0,51 | AllplanAttributes - Positionsnummer_Text: U23
Fensteröffnung | H2 Ebene 0 | 1105Fen0000053608 | m² | 0 | Fensterarbeiten | Fensteröffnung | 0 | 0 | NEW | 1105Wa 0000004595 | 0 | RC 1 | 0,51 | AllplanAttributes - Positionsnummer_Text: U23
Fensteröffnung | H2 Ebene 0 | 1105Fen0000053609 | m² | 0 | Fensterarbeiten | Fensteröffnung | 0 | 0 | NEW | 1105Wa 0000004591 | 0 | RC 1 | 0,51 | AllplanAttributes - Positionsnummer_Text: U23
Fensteröffnung | H2 Ebene 0 | 1105Fen0000053610 | m² | 0 | Fensterarbeiten | Fensteröffnung | 0 | 0 | NEW | 1105Wa 0000004587 | 0 | RC 1 | 0,51 | AllplanAttributes - Positionsnummer_Text: U23
Fensteröffnung | H2 Ebene 0 | 1105Fen0000053646 | m² |  | Fensterarbeiten | Fensteröffnung |  | 0 |  | 1105Wa 0000004655 | 0 | RC 1 | 0,51 | AllplanAttributes - Positionsnummer_Text: U23
Fensteröffnung | H2 Ebene 0 | 1105Fen0000053647 | m³ | 0 | Fensterarbeiten | Fensteröffnung | 0 | 0 |  | 1105Wa 0000004651 | 0 | RC 1 | 0,51 | AllplanAttributes - Positionsnummer_Text: U23
Fensteröffnung | H2 Ebene 0 | 1105Fen0000053648 | m³ | 0 | Fensterarbeiten | Fensteröffnung | 0 | 0 |  | 1105Wa 0000004647 | 0 | RC 1 | 0,51 | AllplanAttributes - Positionsnummer_Text: U23
Fensteröffnung | H2 Ebene 0 | 1105Fen0000053649 | m² | 0 | Fensterarbeiten | Fensteröffnung | 0 | 0 |  | 1105Wa 0000004643 | 0 | RC 1 | 0,51 | AllplanAttributes - Positionsnummer_Text: U23
Fensteröffnung | H2 Ebene 0 | 1105Fen0000053650 | m² | 0 | Fensterarbeiten | Fensteröffnung | 0 | 0 | NEW | 1105Wa 0000004639 | 0 | RC 1 | 0,51 | AllplanAttributes - Positionsnummer_Text: U23
Fensteröffnung | H2 Ebene 0 | 1105Fen0000053651 | m² | 0 | Fensterarbeiten | Fensteröffnung | 0 | 0 | NEW | 1105Wa 0000004635 | 0 | RC 1 | 0,51 | AllplanAttributes - Positionsnummer_Text: U23
Fensteröffnung | H2 Ebene 0 | 1105Fen0000053652 | m² | 0 | Fensterarbeiten | Fensteröffnung | 0 | 0 | NEW | 1105Wa 0000004631 | 0 | RC 1 | 0,51 | AllplanAttributes - Positionsnummer_Text: U23
Fensteröffnung | H2 Ebene 0 | 1105Fen2005780485 | m² | 0 | Fensterarbeiten | Fensteröffnung | 0 | 0 |  | 1105Wa 0000004538 | 0 | RC 1 | 0,51 | AllplanAttributes - Positionsnummer_Text: U23
Fensteröffnung | H2 Ebene 0 | 1105Fen2005780484 | m³ | 0 | Fensterarbeiten | Fensteröffnung | 0 | 0 |  | 1105Wa 0000004543 | 0 | RC 1 | 0,51 | AllplanAttributes - Positionsnummer_Text: U23
Fensteröffnung | H2 Ebene 0 | 1105Fen2005780483 | m³ | 0 | Fensterarbeiten | Fensteröffnung | 0 | 0 |  | 1105Wa 0000004548 | 0 | RC 1 | 0,51 | AllplanAttributes - Positionsnummer_Text: U23
Fensteröffnung | H2 Ebene 0 | 1105Fen2005780482 | m² | 0 | Fensterarbeiten | Fensteröffnung | 0 | 0 |  | 1105Wa 0000004553 | 0 | RC 1 | 0,51 | AllplanAttributes - Positionsnummer_Text: U23
Fensteröffnung | H2 Ebene 0 | 1105Fen2005780481 | m² | 0 | Fensterarbeiten | Fensteröffnung | 0 | 0 | NEW | 1105Wa 0000004558 | 0 | RC 1 | 0,51 | AllplanAttributes - Positionsnummer_Text: U23
Fensteröffnung | H2 Ebene 0 | 1105Fen2005780480 | m² | 0 | Fensterarbeiten | Fensteröffnung | 0 | 0 | NEW | 1105Wa 0000004563 | 0 | RC 1 | 0,51 | AllplanAttributes - Positionsnummer_Text: U23
Fensteröffnung | H2 Ebene 0 | 1105Fen2005780479 | m² | 0 | Fensterarbeiten | Fensteröffnung | 0 | 0 | NEW | 1105Wa 0000004568 | 0 | RC 1 | 0,51 | AllplanAttributes - Positionsnummer_Text: U23
Fensteröffnung | H2 Ebene 0 | 1105Fen0000051333 | m² | 0 | Fensterarbeiten | Fensteröffnung | 0 | 0 |  | 1105Wa 0000003844 | 0 | RC 1 | 0,51 | AllplanAttributes - Positionsnummer_Text: U23
Fensteröffnung | H2 Ebene 0 | 1105Fen0000051578 | m² | 0 | Fensterarbeiten | Fensteröffnung | 0 | 0 |  | 1105Wa 0000003844 | 0 | RC 1 | 0,51 | AllplanAttributes - Positionsnummer_Text: U23
Fensteröffnung | H2 Ebene 0 | 1105Fen0000085356 | m² | 0 | Fensterarbeiten | Fensteröffnung | 0 | 0 |  | 1105Wa 0000003844 | 0 | RC 1 | 0,51 | AllplanAttributes - Positionsnummer_Text: U23
Fensteröffnung | H2 Ebene 0 | 1105Fen0000051463 | m² | 0 | Fensterarbeiten | Fensteröffnung | 0 | 0 |  | 1105Wa 0000003844 | 0 | RC 1 | 0,51 | AllplanAttributes - Positionsnummer_Text: U23
Fensteröffnung | H2 Ebene 0 | 1105Fen0000051260 | m² | 0 | Fensterarbeiten | Fensteröffnung | 0 | 0 |  | 1105Wa 0000003844 | 0 | RC 1 | 0,51 | AllplanAttributes - Positionsnummer_Text: U23
Fensteröffnung | H2 Ebene 0 | 1105Fen0000051421 | m² | 0 | Fensterarbeiten | Fensteröffnung | 0 | 0 |  | 1105Wa 0000003844 | 0 | RC 1 | 0,51 | AllplanAttributes - Positionsnummer_Text: U23
Fensteröffnung | H2 Ebene 0 | 1105Fen0000051332 | m³ | 0 | Fensterarbeiten | Fensteröffnung | 0 | 0 |  | 1105Wa 0000003834 | 0 | RC 1 | 0,51 | AllplanAttributes - Positionsnummer_Text: U23
Fensteröffnung | H2 Ebene 0 | 1105Fen0000051577 | m³ | 0 | Fensterarbeiten | Fensteröffnung | 0 | 0 |  | 1105Wa 0000003834 | 0 | RC 1 | 0,51 | AllplanAttributes - Positionsnummer_Text: U23
Fensteröffnung | H2 Ebene 0 | 1105Fen0000085354 | m³ | 0 | Fensterarbeiten | Fensteröffnung | 0 | 0 |  | 1105Wa 0000003834 | 0 | RC 1 | 0,51 | AllplanAttributes - Positionsnummer_Text: U23
Fensteröffnung | H2 Ebene 0 | 1105Fen0000051462 | m³ | 0 | Fensterarbeiten | Fensteröffnung | 0 | 0 |  | 1105Wa 0000003834 | 0 | RC 1 | 0,51 | AllplanAttributes - Positionsnummer_Text: U23
Fensteröffnung | H2 Ebene 0 | 1105Fen0000051259 | m³ | 0 | Fensterarbeiten | Fensteröffnung | 0 | 0 |  | 1105Wa 0000003834 | 0 | RC 1 | 0,51 | AllplanAttributes - Positionsnummer_Text: U23
Fensteröffnung | H2 Ebene 0 | 1105Fen0000051420 | m³ | 0 | Fensterarbeiten | Fensteröffnung | 0 | 0 |  | 1105Wa 0000003834 | 0 | RC 1 | 0,51 | AllplanAttributes - Positionsnummer_Text: U23
Fensteröffnung | H2 Ebene 0 | 1105Fen0000051331 | m³ | 0 | Fensterarbeiten | Fensteröffnung | 0 | 0 |  | 1105Wa 0000003824 | 0 | RC 1 | 0,51 | AllplanAttributes - Positionsnummer_Text: U23
Fensteröffnung | H2 Ebene 0 | 1105Fen0000051576 | m³ | 0 | Fensterarbeiten | Fensteröffnung | 0 | 0 |  | 1105Wa 0000003824 | 0 | RC 1 | 0,51 | AllplanAttributes - Positionsnummer_Text: U23
Fensteröffnung | H2 Ebene 0 | 1105Fen0000085352 | m³ | 0 | Fensterarbeiten | Fensteröffnung | 0 | 0 |  | 1105Wa 0000003824 | 0 | RC 1 | 0,51 | AllplanAttributes - Positionsnummer_Text: U23
Fensteröffnung | H2 Ebene 0 | 1105Fen0000051461 | m³ | 0 | Fensterarbeiten | Fensteröffnung | 0 | 0 |  | 1105Wa 0000003824 | 0 | RC 1 | 0,51 | AllplanAttributes - Positionsnummer_Text: U23
Fensteröffnung | H2 Ebene 0 | 1105Fen0000051258 | m³ | 0 | Fensterarbeiten | Fensteröffnung | 0 | 0 |  | 1105Wa 0000003824 | 0 | RC 1 | 0,51 | AllplanAttributes - Positionsnummer_Text: U23
Fensteröffnung | H2 Ebene 0 | 1105Fen0000051419 | m³ | 0 | Fensterarbeiten | Fensteröffnung | 0 | 0 |  | 1105Wa 0000003824 | 0 | RC 1 | 0,51 | AllplanAttributes - Positionsnummer_Text: U23
Fensteröffnung | H2 Ebene 0 | 1105Fen0000051330 | m² | 0 | Fensterarbeiten | Fensteröffnung | 0 | 0 |  | 1105Wa 0000003814 | 0 | RC 1 | 0,51 | AllplanAttributes - Positionsnummer_Text: U23
Fensteröffnung | H2 Ebene 0 | 1105Fen0000051575 | m² | 0 | Fensterarbeiten | Fensteröffnung | 0 | 0 |  | 1105Wa 0000003814 | 0 | RC 1 | 0,51 | AllplanAttributes - Positionsnummer_Text: U23
Fensteröffnung | H2 Ebene 0 | 1105Fen0000085350 | m² | 0 | Fensterarbeiten | Fensteröffnung | 0 | 0 |  | 1105Wa 0000003814 | 0 | RC 1 | 0,51 | AllplanAttributes - Positionsnummer_Text: U23
Fensteröffnung | H2 Ebene 0 | 1105Fen0000051460 | m² | 0 | Fensterarbeiten | Fensteröffnung | 0 | 0 |  | 1105Wa 0000003814 | 0 | RC 1 | 0,51 | AllplanAttributes - Positionsnummer_Text: U23
Fensteröffnung | H2 Ebene 0 | 1105Fen0000051257 | m² | 0 | Fensterarbeiten | Fensteröffnung | 0 | 0 |  | 1105Wa 0000003814 | 0 | RC 1 | 0,51 | AllplanAttributes - Positionsnummer_Text: U23
Fensteröffnung | H2 Ebene 0 | 1105Fen0000051418 | m² | 0 | Fensterarbeiten | Fensteröffnung | 0 | 0 |  | 1105Wa 0000003814 | 0 | RC 1 | 0,51 | AllplanAttributes - Positionsnummer_Text: U23
Fensteröffnung | H2 Ebene 0 | 1105Fen0000051329 | m² | 0 | Fensterarbeiten | Fensteröffnung | 0 | 0 | NEW | 1105Wa 0000003804 | 0 | RC 1 | 0,51 | AllplanAttributes - Positionsnummer_Text: U23
Fensteröffnung | H2 Ebene 0 | 1105Fen0000051574 | m² | 0 | Fensterarbeiten | Fensteröffnung | 0 | 0 | NEW | 1105Wa 0000003804 | 0 | RC 1 | 0,51 | AllplanAttributes - Positionsnummer_Text: U23
Fensteröffnung | H2 Ebene 0 | 1105Fen0000085348 | m² | 0 | Fensterarbeiten | Fensteröffnung | 0 | 0 | NEW | 1105Wa 0000003804 | 0 | RC 1 | 0,51 | AllplanAttributes - Positionsnummer_Text: U23
Fensteröffnung | H2 Ebene 0 | 1105Fen0000051459 | m² | 0 | Fensterarbeiten | Fensteröffnung | 0 | 0 | NEW | 1105Wa 0000003804 | 0 | RC 1 | 0,51 | AllplanAttributes - Positionsnummer_Text: U23
Fensteröffnung | H2 Ebene 0 | 1105Fen0000051256 | m² | 0 | Fensterarbeiten | Fensteröffnung | 0 | 0 | NEW | 1105Wa 0000003804 | 0 | RC 1 | 0,51 | AllplanAttributes - Positionsnummer_Text: U23
Fensteröffnung | H2 Ebene 0 | 1105Fen0000051417 | m² | 0 | Fensterarbeiten | Fensteröffnung | 0 | 0 | NEW | 1105Wa 0000003804 | 0 | RC 1 | 0,51 | AllplanAttributes - Positionsnummer_Text: U23
Fensteröffnung | H2 Ebene 0 | 1105Fen0000051328 | m² | 0 | Fensterarbeiten | Fensteröffnung | 0 | 0 | NEW | 1105Wa 0000003794 | 0 | RC 1 | 0,51 | AllplanAttributes - Positionsnummer_Text: U23
Fensteröffnung | H2 Ebene 0 | 1105Fen0000051573 | m² | 0 | Fensterarbeiten | Fensteröffnung | 0 | 0 | NEW | 1105Wa 0000003794 | 0 | RC 1 | 0,51 | AllplanAttributes - Positionsnummer_Text: U23
Fensteröffnung | H2 Ebene 0 | 1105Fen0000085346 | m² | 0 | Fensterarbeiten | Fensteröffnung | 0 | 0 | NEW | 1105Wa 0000003794 | 0 | RC 1 | 0,51 | AllplanAttributes - Positionsnummer_Text: U23
Fensteröffnung | H2 Ebene 0 | 1105Fen0000051458 | m² | 0 | Fensterarbeiten | Fensteröffnung | 0 | 0 | NEW | 1105Wa 0000003794 | 0 | RC 1 | 0,51 | AllplanAttributes - Positionsnummer_Text: U23
Fensteröffnung | H2 Ebene 0 | 1105Fen0000051255 | m² | 0 | Fensterarbeiten | Fensteröffnung | 0 | 0 | NEW | 1105Wa 0000003794 | 0 | RC 1 | 0,51 | AllplanAttributes - Positionsnummer_Text: U23
Fensteröffnung | H2 Ebene 0 | 1105Fen0000051416 | m² | 0 | Fensterarbeiten | Fensteröffnung | 0 | 0 | NEW | 1105Wa 0000003794 | 0 | RC 1 | 0,51 | AllplanAttributes - Positionsnummer_Text: U23
Fensteröffnung | H2 Ebene 0 | 1105Fen0000051327 | m² | 0 | Fensterarbeiten | Fensteröffnung | 0 | 0 | NEW | 1105Wa 0000003784 | 0 | RC 1 | 0,51 | AllplanAttributes - Positionsnummer_Text: U23
Fensteröffnung | H2 Ebene 0 | 1105Fen0000051572 | m² | 0 | Fensterarbeiten | Fensteröffnung | 0 | 0 | NEW | 1105Wa 0000003784 | 0 | RC 1 | 0,51 | AllplanAttributes - Positionsnummer_Text: U23
Fensteröffnung | H2 Ebene 0 | 1105Fen0000085344 | m² | 0 | Fensterarbeiten | Fensteröffnung | 0 | 0 | NEW | 1105Wa 0000003784 | 0 | RC 1 | 0,51 | AllplanAttributes - Positionsnummer_Text: U23
Fensteröffnung | H2 Ebene 0 | 1105Fen0000051457 | m² | 0 | Fensterarbeiten | Fensteröffnung | 0 | 0 | NEW | 1105Wa 0000003784 | 0 | RC 1 | 0,51 | AllplanAttributes - Positionsnummer_Text: U23
Fensteröffnung | H2 Ebene 0 | 1105Fen0000051254 | m² | 0 | Fensterarbeiten | Fensteröffnung | 0 | 0 | NEW | 1105Wa 0000003784 | 0 | RC 1 | 0,51 | AllplanAttributes - Positionsnummer_Text: U23
Fensteröffnung | H2 Ebene 0 | 1105Fen0000051415 | m² | 0 | Fensterarbeiten | Fensteröffnung | 0 | 0 | NEW | 1105Wa 0000003784 | 0 | RC 1 | 0,51 | AllplanAttributes - Positionsnummer_Text: U23
Fensteröffnung | H2 Ebene 0 | 1105Fen2005780289 | m² | 0 | Fensterarbeiten | Fensteröffnung | 0 | 0 |  | 1105Wa 0000004538 | 0 | RC 1 | 0,51 | AllplanAttributes - Positionsnummer_Text: U23
Fensteröffnung | H2 Ebene 0 | 1105Fen2005780371 | m² | 0 | Fensterarbeiten | Fensteröffnung | 0 | 0 |  | 1105Wa 0000004538 | 0 | RC 1 | 0,51 | AllplanAttributes - Positionsnummer_Text: U23
Fensteröffnung | H2 Ebene 0 | 1105Fen2005780288 | m³ | 0 | Fensterarbeiten | Fensteröffnung | 0 | 0 |  | 1105Wa 0000004543 | 0 | RC 1 | 0,51 | AllplanAttributes - Positionsnummer_Text: U23
Fensteröffnung | H2 Ebene 0 | 1105Fen2005780370 | m³ | 0 | Fensterarbeiten | Fensteröffnung | 0 | 0 |  | 1105Wa 0000004543 | 0 | RC 1 | 0,51 | AllplanAttributes - Positionsnummer_Text: U23
Fensteröffnung | H2 Ebene 0 | 1105Fen2005780287 | m³ | 0 | Fensterarbeiten | Fensteröffnung | 0 | 0 |  | 1105Wa 0000004548 | 0 | RC 1 | 0,51 | AllplanAttributes - Positionsnummer_Text: U23
Fensteröffnung | H2 Ebene 0 | 1105Fen2005780369 | m³ | 0 | Fensterarbeiten | Fensteröffnung | 0 | 0 |  | 1105Wa 0000004548 | 0 | RC 1 | 0,51 | AllplanAttributes - Positionsnummer_Text: U23
Fensteröffnung | H2 Ebene 0 | 1105Fen2005780286 | m² | 0 | Fensterarbeiten | Fensteröffnung | 0 | 0 |  | 1105Wa 0000004553 | 0 | RC 1 | 0,51 | AllplanAttributes - Positionsnummer_Text: U23
Fensteröffnung | H2 Ebene 0 | 1105Fen2005780368 | m² | 0 | Fensterarbeiten | Fensteröffnung | 0 | 0 |  | 1105Wa 0000004553 | 0 | RC 1 | 0,51 | AllplanAttributes - Positionsnummer_Text: U23
Fensteröffnung | H2 Ebene 0 | 1105Fen2005780285 | m² | 0 | Fensterarbeiten | Fensteröffnung | 0 | 0 | NEW | 1105Wa 0000004558 | 0 | RC 1 | 0,51 | AllplanAttributes - Positionsnummer_Text: U23
Fensteröffnung | H2 Ebene 0 | 1105Fen2005780367 | m² | 0 | Fensterarbeiten | Fensteröffnung | 0 | 0 | NEW | 1105Wa 0000004558 | 0 | RC 1 | 0,51 | AllplanAttributes - Positionsnummer_Text: U23
Fensteröffnung | H2 Ebene 0 | 1105Fen2005780284 | m² | 0 | Fensterarbeiten | Fensteröffnung | 0 | 0 | NEW | 1105Wa 0000004563 | 0 | RC 1 | 0,51 | AllplanAttributes - Positionsnummer_Text: U23
Fensteröffnung | H2 Ebene 0 | 1105Fen2005780366 | m² | 0 | Fensterarbeiten | Fensteröffnung | 0 | 0 | NEW | 1105Wa 0000004563 | 0 | RC 1 | 0,51 | AllplanAttributes - Positionsnummer_Text: U23
Fensteröffnung | H2 Ebene 0 | 1105Fen2005780283 | m² | 0 | Fensterarbeiten | Fensteröffnung | 0 | 0 | NEW | 1105Wa 0000004568 | 0 | RC 1 | 0,51 | AllplanAttributes - Positionsnummer_Text: U23
Fensteröffnung | H2 Ebene 0 | 1105Fen2005780365 | m² | 0 | Fensterarbeiten | Fensteröffnung | 0 | 0 | NEW | 1105Wa 0000004568 | 0 | RC 1 | 0,51 | AllplanAttributes - Positionsnummer_Text: U23
Fensteröffnung | H2 Ebene 0 | 1105Fen0000053229 | m² | 0 | Fensterarbeiten | Fensteröffnung | 0 | 0 |  | 1105Wa 0000004538 | 0 | RC 1 | 0,51 | AllplanAttributes - Positionsnummer_Text: U23
Fensteröffnung | H2 Ebene 0 | 1105Fen2005780179 | m² | 0 | Fensterarbeiten | Fensteröffnung | 0 | 0 |  | 1105Wa 0000004538 | 0 | RC 1 | 0,51 | AllplanAttributes - Positionsnummer_Text: U23
Fensteröffnung | H2 Ebene 0 | 1105Fen0000053228 | m³ | 0 | Fensterarbeiten | Fensteröffnung | 0 | 0 |  | 1105Wa 0000004543 | 0 | RC 1 | 0,51 | AllplanAttributes - Positionsnummer_Text: U23
Fensteröffnung | H2 Ebene 0 | 1105Fen2005780178 | m³ | 0 | Fensterarbeiten | Fensteröffnung | 0 | 0 |  | 1105Wa 0000004543 | 0 | RC 1 | 0,51 | AllplanAttributes - Positionsnummer_Text: U23
Fensteröffnung | H2 Ebene 0 | 1105Fen0000053227 | m³ | 0 | Fensterarbeiten | Fensteröffnung | 0 | 0 |  | 1105Wa 0000004548 | 0 | RC 1 | 0,51 | AllplanAttributes - Positionsnummer_Text: U23
Fensteröffnung | H2 Ebene 0 | 1105Fen2005780177 | m³ | 0 | Fensterarbeiten | Fensteröffnung | 0 | 0 |  | 1105Wa 0000004548 | 0 | RC 1 | 0,51 | AllplanAttributes - Positionsnummer_Text: U23
Fensteröffnung | H2 Ebene 0 | 1105Fen0000053226 | m² | 0 | Fensterarbeiten | Fensteröffnung | 0 | 0 |  | 1105Wa 0000004553 | 0 | RC 1 | 0,51 | AllplanAttributes - Positionsnummer_Text: U23
Fensteröffnung | H2 Ebene 0 | 1105Fen2005780176 | m² | 0 | Fensterarbeiten | Fensteröffnung | 0 | 0 |  | 1105Wa 0000004553 | 0 | RC 1 | 0,51 | AllplanAttributes - Positionsnummer_Text: U23
Fensteröffnung | H2 Ebene 0 | 1105Fen0000053225 | m² | 0 | Fensterarbeiten | Fensteröffnung | 0 | 0 | NEW | 1105Wa 0000004558 | 0 | RC 1 | 0,51 | AllplanAttributes - Positionsnummer_Text: U23
Fensteröffnung | H2 Ebene 0 | 1105Fen2005780175 | m² | 0 | Fensterarbeiten | Fensteröffnung | 0 | 0 | NEW | 1105Wa 0000004558 | 0 | RC 1 | 0,51 | AllplanAttributes - Positionsnummer_Text: U23
Fensteröffnung | H2 Ebene 0 | 1105Fen0000053224 | m² | 0 | Fensterarbeiten | Fensteröffnung | 0 | 0 | NEW | 1105Wa 0000004563 | 0 | RC 1 | 0,51 | AllplanAttributes - Positionsnummer_Text: U23
Fensteröffnung | H2 Ebene 0 | 1105Fen2005780174 | m² | 0 | Fensterarbeiten | Fensteröffnung | 0 | 0 | NEW | 1105Wa 0000004563 | 0 | RC 1 | 0,51 | AllplanAttributes - Positionsnummer_Text: U23
Fensteröffnung | H2 Ebene 0 | 1105Fen0000053223 | m² | 0 | Fensterarbeiten | Fensteröffnung | 0 | 0 | NEW | 1105Wa 0000004568 | 0 | RC 1 | 0,51 | AllplanAttributes - Positionsnummer_Text: U23
Fensteröffnung | H2 Ebene 0 | 1105Fen2005780173 | m² | 0 | Fensterarbeiten | Fensteröffnung | 0 | 0 | NEW | 1105Wa 0000004568 | 0 | RC 1 | 0,51 | AllplanAttributes - Positionsnummer_Text: U23
Fensteröffnung | H2 Ebene 0 | 1105Fen2005789659 | m² | 0 | Fensterarbeiten | Fensteröffnung | 0 | 0 |  | 1105Wa 0000003844 | 0 | RC 1 | 0,51 | AllplanAttributes - Positionsnummer_Text: U23
Türöffnung | H2 Ebene 0 | 1105Tür2005789757 | m² | 0 | Trockenbauarbeiten | Türöffnung | 0 | 0 | NEW | 1105Wa 0000180626 | 0 | RC 1 | 0,51 | AllplanAttributes - Codetext: Codetext; Türanschlag: DIN L; Positionsnummer_Text: U23; Pset_OpeningElementCommon - FireExit: no; Reference: Codetext
Fensteröffnung | H2 Ebene 0 | 1105Fen2005789167 | m² | 0 | Fensterarbeiten | Fensteröffnung | 0 | 0 |  | 1105Wa 0000003844 | 0 | RC 1 | 0,51 | AllplanAttributes - Positionsnummer_Text: U23
Fensteröffnung | H2 Ebene 0 | 1105Fen2005789658 | m³ | 0 | Fensterarbeiten | Fensteröffnung | 0 | 0 |  | 1105Wa 0000003834 | 0 | RC 1 | 0,51 | AllplanAttributes - Positionsnummer_Text: U23
Türöffnung | H2 Ebene 0 | 1105Tür2005789756 | m³ | 0 | Trockenbauarbeiten | Türöffnung | 0 | 0 | NEW | 1105Wa 0000180627 | 0 | RC 1 | 0,51 | AllplanAttributes - ash D_Detailverweis: FSLH2; ash D_Plannummer: D832; Türanschlag: DIN L; Positionsnummer_Text: U23
Fensteröffnung | H2 Ebene 0 | 1105Fen2005789166 | m³ | 0 | Fensterarbeiten | Fensteröffnung | 0 | 0 |  | 1105Wa 0000003834 | 0 | RC 1 | 0,51 | AllplanAttributes - Positionsnummer_Text: U23
Fensteröffnung | H2 Ebene 0 | 1105Fen2005789657 | m³ | 0 | Fensterarbeiten | Fensteröffnung | 0 | 0 |  | 1105Wa 0000003824 | 0 | RC 1 | 0,51 | AllplanAttributes - Positionsnummer_Text: U23
Türöffnung | H2 Ebene 0 | 1105Tür2005789755 | m³ | 0 | Trockenbauarbeiten | Türöffnung | 0 | 0 | NEW | 1105Wa 0000180628 | 0 | RC 1 | 0,51 | AllplanAttributes - Türanschlag: DIN L; Positionsnummer_Text: U23
Fensteröffnung | H2 Ebene 0 | 1105Fen2005789165 | m³ | 0 | Fensterarbeiten | Fensteröffnung | 0 | 0 |  | 1105Wa 0000003824 | 0 | RC 1 | 0,51 | AllplanAttributes - Positionsnummer_Text: U23
Fensteröffnung | H2 Ebene 0 | 1105Fen2005789656 | m² | 0 | Fensterarbeiten | Fensteröffnung | 0 | 0 |  | 1105Wa 0000003814 | 0 | RC 1 | 0,51 | AllplanAttributes - Positionsnummer_Text: U23
Türöffnung | H2 Ebene 0 | 1105Tür2005789754 | m² | 0 | Trockenbauarbeiten | Türöffnung | 0 | 0 | NEW | 1105Wa 0000180629 | 0 | RC 1 | 0,51 | AllplanAttributes - Türanschlag: DIN L; Positionsnummer_Text: U23
Fensteröffnung | H2 Ebene 0 | 1105Fen2005789164 | m² | 0 | Fensterarbeiten | Fensteröffnung | 0 | 0 |  | 1105Wa 0000003814 | 0 | RC 1 | 0,51 | AllplanAttributes - Positionsnummer_Text: U23
Fensteröffnung | H2 Ebene 0 | 1105Fen2005789655 | m² | 0 | Fensterarbeiten | Fensteröffnung | 0 | 0 | NEW | 1105Wa 0000003804 | 0 | RC 1 | 0,51 | AllplanAttributes - Positionsnummer_Text: U23
Türöffnung | H2 Ebene 0 | 1105Tür2005789753 | m² | 0 | Trockenbauarbeiten | Türöffnung | 0 | 0 | NEW | 1105Wa 0000180630 | 0 | RC 1 | 0,51 | AllplanAttributes - Türanschlag: DIN L; Positionsnummer_Text: U23
Fensteröffnung | H2 Ebene 0 | 1105Fen2005789163 | m² | 0 | Fensterarbeiten | Fensteröffnung | 0 | 0 | NEW | 1105Wa 0000003804 | 0 | RC 1 | 0,51 | AllplanAttributes - Positionsnummer_Text: U23
Fensteröffnung | H2 Ebene 0 | 1105Fen2005789654 | m² | 0 | Fensterarbeiten | Fensteröffnung | 0 | 0 | NEW | 1105Wa 0000003794 | 0 | RC 1 | 0,51 | AllplanAttributes - Positionsnummer_Text: U23
Türöffnung | H2 Ebene 0 | 1105Tür2005789752 | m² | 0 | Trockenbauarbeiten | Türöffnung | 0 | 0 | NEW | 1105Wa 0000180631 | 0 | RC 1 | 0,51 | AllplanAttributes - Türanschlag: DIN L; Positionsnummer_Text: U23
Fensteröffnung | H2 Ebene 0 | 1105Fen2005789162 | m² | 0 | Fensterarbeiten | Fensteröffnung | 0 | 0 | NEW | 1105Wa 0000003794 | 0 | RC 1 | 0,51 | AllplanAttributes - Positionsnummer_Text: U23
Fensteröffnung | H2 Ebene 0 | 1105Fen2005789653 | m² | 0 | Fensterarbeiten | Fensteröffnung | 0 | 0 | NEW | 1105Wa 0000003784 | 0 | RC 1 | 0,51 | AllplanAttributes - Positionsnummer_Text: U23
Türöffnung | H2 Ebene 0 | 1105Tür2005789751 | m² | 0 | Trockenbauarbeiten | Türöffnung | 0 | 0 | NEW | 1105Wa 0000180632 | 0 | RC 1 | 0,51 | AllplanAttributes - Türanschlag: DIN L; Positionsnummer_Text: U23
Fensteröffnung | H2 Ebene 0 | 1105Fen2005789161 | m² | 0 | Fensterarbeiten | Fensteröffnung | 0 | 0 | NEW | 1105Wa 0000003784 | 0 | RC 1 | 0,51 | AllplanAttributes - Positionsnummer_Text: U23
Fensteröffnung | H2 Ebene 0 | 1105Fen0811564238 | m² |  | Fensterarbeiten | Fensteröffnung |  | 0 |  | 1105Wa 0811564258 | 0 | RC 1 | 0,51 | AllplanAttributes - Positionsnummer_Text: U23
Fensteröffnung | H2 Ebene 0 | 1105Fen0811564245 | m² |  | Fensterarbeiten | Fensteröffnung |  | 0 |  | 1105Wa 0811564258 | 0 | RC 1 | 0,51 | AllplanAttributes - Positionsnummer_Text: U23
Fensteröffnung | H2 Ebene 0 | 1105Fen0811564239 | m³ | 0 | Fensterarbeiten | Fensteröffnung | 0 | 0 |  | 1105Wa 0811564257 | 0 | RC 1 | 0,51 | AllplanAttributes - Positionsnummer_Text: U23
Fensteröffnung | H2 Ebene 0 | 1105Fen0811564246 | m³ | 0 | Fensterarbeiten | Fensteröffnung | 0 | 0 |  | 1105Wa 0811564257 | 0 | RC 1 | 0,51 | AllplanAttributes - Positionsnummer_Text: U23
Fensteröffnung | H2 Ebene 0 | 1105Fen0811564240 | m³ | 0 | Fensterarbeiten | Fensteröffnung | 0 | 0 |  | 1105Wa 0811564256 | 0 | RC 1 | 0,51 | AllplanAttributes - Positionsnummer_Text: U23
Fensteröffnung | H2 Ebene 0 | 1105Fen0811564247 | m³ | 0 | Fensterarbeiten | Fensteröffnung | 0 | 0 |  | 1105Wa 0811564256 | 0 | RC 1 | 0,51 | AllplanAttributes - Positionsnummer_Text: U23
Fensteröffnung | H2 Ebene 0 | 1105Fen0811564241 | m² | 0 | Fensterarbeiten | Fensteröffnung | 0 | 0 |  | 1105Wa 0811564255 | 0 | RC 1 | 0,51 | AllplanAttributes - Positionsnummer_Text: U23
Fensteröffnung | H2 Ebene 0 | 1105Fen0811564248 | m² | 0 | Fensterarbeiten | Fensteröffnung | 0 | 0 |  | 1105Wa 0811564255 | 0 | RC 1 | 0,51 | AllplanAttributes - Positionsnummer_Text: U23
Fensteröffnung | H2 Ebene 0 | 1105Fen0811564242 | m² | 0 | Fensterarbeiten | Fensteröffnung | 0 | 0 | NEW | 1105Wa 0811564254 | 0 | RC 1 | 0,51 | AllplanAttributes - Positionsnummer_Text: U23
Fensteröffnung | H2 Ebene 0 | 1105Fen0811564249 | m² | 0 | Fensterarbeiten | Fensteröffnung | 0 | 0 | NEW | 1105Wa 0811564254 | 0 | RC 1 | 0,51 | AllplanAttributes - Positionsnummer_Text: U23
Fensteröffnung | H2 Ebene 0 | 1105Fen0811564243 | m² | 0 | Fensterarbeiten | Fensteröffnung | 0 | 0 | NEW | 1105Wa 0811564253 | 0 | RC 1 | 0,51 | AllplanAttributes - Positionsnummer_Text: U23
Fensteröffnung | H2 Ebene 0 | 1105Fen0811564250 | m² | 0 | Fensterarbeiten | Fensteröffnung | 0 | 0 | NEW | 1105Wa 0811564253 | 0 | RC 1 | 0,51 | AllplanAttributes - Positionsnummer_Text: U23
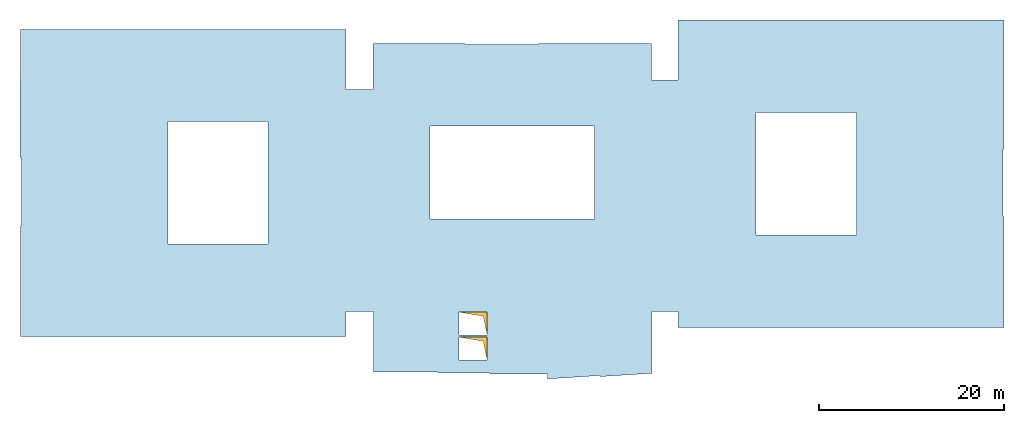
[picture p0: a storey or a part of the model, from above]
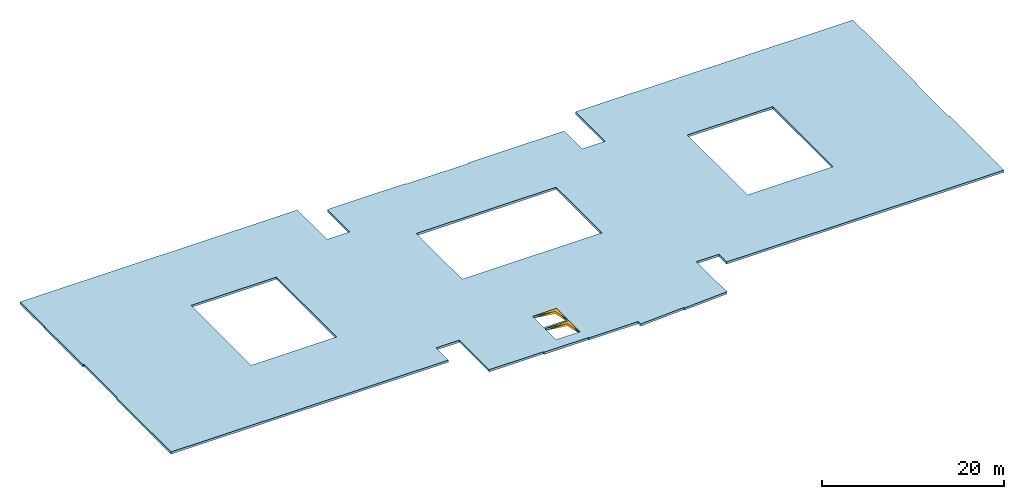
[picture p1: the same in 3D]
Properties of the parts of a building model (IFC4), part 40 of 80

# IfcOpeningElement: Opening (3497)
Name | In | Allright_Bauteil_ID | Abrechnungsart | Versatz_oben | Gewerk | Objektname | Versatz_unten | OKFF | Status | P_ID | AllplanAttributes, Feuerwiderstandsklasse | Sicherheitsklasse | g-Wert
Fensteröffnung | H2 Ebene 0 | 1105Fen0811564244 | m² | 0 | Fensterarbeiten | Fensteröffnung | 0 | 0 | NEW | 1105Wa 0811564252 | 0 | RC 1 | 0,51 | AllplanAttributes - Positionsnummer_Text: U23
Fensteröffnung | H2 Ebene 0 | 1105Fen0811564251 | m² | 0 | Fensterarbeiten | Fensteröffnung | 0 | 0 | NEW | 1105Wa 0811564252 | 0 | RC 1 | 0,51 | AllplanAttributes - Positionsnummer_Text: U23
Fensteröffnung | H2 Ebene 0 | 1105Fen2005779310 | m² | 0 | Fensterarbeiten | Fensteröffnung | 0 | 0 |  | 1105Wa 0000003844 | 0 | RC 1 | 0,51 | AllplanAttributes - Positionsnummer_Text: U23
Fensteröffnung | H2 Ebene 0 | 1105Fen2005779392 | m² | 0 | Fensterarbeiten | Fensteröffnung | 0 | 0 |  | 1105Wa 0000003844 | 0 | RC 1 | 0,51 | AllplanAttributes - Positionsnummer_Text: U23
Fensteröffnung | H2 Ebene 0 | 1105Fen2005779474 | m² | 0 | Fensterarbeiten | Fensteröffnung | 0 | 0 |  | 1105Wa 0000003844 | 0 | RC 1 | 0,51 | AllplanAttributes - Positionsnummer_Text: U23
Türöffnung | H2 Ebene 0 | 1105Tür0000085523 | m² |  | Trockenbauarbeiten | Türöffnung |  | 0 | NEW | 1105Wa 0000004015 | 0 | RC 1 | 0,51 | AllplanAttributes - Codetext: Codetext; Türanschlag: DIN L; Positionsnummer_Text: U23; Pset_OpeningElementCommon - FireExit: no; Reference: Codetext
Fensteröffnung | H2 Ebene 0 | 1105Fen2005779309 | m³ | 0 | Fensterarbeiten | Fensteröffnung | 0 | 0 |  | 1105Wa 0000003834 | 0 | RC 1 | 0,51 | AllplanAttributes - Positionsnummer_Text: U23
Fensteröffnung | H2 Ebene 0 | 1105Fen2005779391 | m³ | 0 | Fensterarbeiten | Fensteröffnung | 0 | 0 |  | 1105Wa 0000003834 | 0 | RC 1 | 0,51 | AllplanAttributes - Positionsnummer_Text: U23
Fensteröffnung | H2 Ebene 0 | 1105Fen2005779473 | m³ | 0 | Fensterarbeiten | Fensteröffnung | 0 | 0 |  | 1105Wa 0000003834 | 0 | RC 1 | 0,51 | AllplanAttributes - Positionsnummer_Text: U23
Türöffnung | H2 Ebene 0 | 1105Tür0000085521 | m³ | 0 | Trockenbauarbeiten | Türöffnung | 0 | 0 | NEW | 1105Wa 0000004020 | 0 | RC 1 | 0,51 | AllplanAttributes - Türanschlag: DIN L; Positionsnummer_Text: U23
Fensteröffnung | H2 Ebene 0 | 1105Fen2005779308 | m³ | 0 | Fensterarbeiten | Fensteröffnung | 0 | 0 |  | 1105Wa 0000003824 | 0 | RC 1 | 0,51 | AllplanAttributes - Positionsnummer_Text: U23
Fensteröffnung | H2 Ebene 0 | 1105Fen2005779390 | m³ | 0 | Fensterarbeiten | Fensteröffnung | 0 | 0 |  | 1105Wa 0000003824 | 0 | RC 1 | 0,51 | AllplanAttributes - Positionsnummer_Text: U23
Fensteröffnung | H2 Ebene 0 | 1105Fen2005779472 | m³ | 0 | Fensterarbeiten | Fensteröffnung | 0 | 0 |  | 1105Wa 0000003824 | 0 | RC 1 | 0,51 | AllplanAttributes - Positionsnummer_Text: U23
Türöffnung | H2 Ebene 0 | 1105Tür0000085519 | m³ | 0 | Trockenbauarbeiten | Türöffnung | 0 | 0 | NEW | 1105Wa 0000004024 | 0 | RC 1 | 0,51 | AllplanAttributes - Türanschlag: DIN L; Positionsnummer_Text: U23
Fensteröffnung | H2 Ebene 0 | 1105Fen2005779307 | m² | 0 | Fensterarbeiten | Fensteröffnung | 0 | 0 |  | 1105Wa 0000003814 | 0 | RC 1 | 0,51 | AllplanAttributes - Positionsnummer_Text: U23
Fensteröffnung | H2 Ebene 0 | 1105Fen2005779389 | m² | 0 | Fensterarbeiten | Fensteröffnung | 0 | 0 |  | 1105Wa 0000003814 | 0 | RC 1 | 0,51 | AllplanAttributes - Positionsnummer_Text: U23
Fensteröffnung | H2 Ebene 0 | 1105Fen2005779471 | m² | 0 | Fensterarbeiten | Fensteröffnung | 0 | 0 |  | 1105Wa 0000003814 | 0 | RC 1 | 0,51 | AllplanAttributes - Positionsnummer_Text: U23
Türöffnung | H2 Ebene 0 | 1105Tür0000085517 | m² | 0 | Trockenbauarbeiten | Türöffnung | 0 | 0 | NEW | 1105Wa 0000004029 | 0 | RC 1 | 0,51 | AllplanAttributes - Türanschlag: DIN L; Positionsnummer_Text: U23
Fensteröffnung | H2 Ebene 0 | 1105Fen2005779306 | m² | 0 | Fensterarbeiten | Fensteröffnung | 0 | 0 | NEW | 1105Wa 0000003804 | 0 | RC 1 | 0,51 | AllplanAttributes - Positionsnummer_Text: U23
Fensteröffnung | H2 Ebene 0 | 1105Fen2005779388 | m² | 0 | Fensterarbeiten | Fensteröffnung | 0 | 0 | NEW | 1105Wa 0000003804 | 0 | RC 1 | 0,51 | AllplanAttributes - Positionsnummer_Text: U23
Fensteröffnung | H2 Ebene 0 | 1105Fen2005779470 | m² | 0 | Fensterarbeiten | Fensteröffnung | 0 | 0 | NEW | 1105Wa 0000003804 | 0 | RC 1 | 0,51 | AllplanAttributes - Positionsnummer_Text: U23
Türöffnung | H2 Ebene 0 | 1105Tür0000085515 | m² | 0 | Trockenbauarbeiten | Türöffnung | 0 | 0 | NEW | 1105Wa 0000004034 | 0 | RC 1 | 0,51 | AllplanAttributes - Türanschlag: DIN L; Positionsnummer_Text: U23
Fensteröffnung | H2 Ebene 0 | 1105Fen2005779305 | m² | 0 | Fensterarbeiten | Fensteröffnung | 0 | 0 | NEW | 1105Wa 0000003794 | 0 | RC 1 | 0,51 | AllplanAttributes - Positionsnummer_Text: U23
Fensteröffnung | H2 Ebene 0 | 1105Fen2005779387 | m² | 0 | Fensterarbeiten | Fensteröffnung | 0 | 0 | NEW | 1105Wa 0000003794 | 0 | RC 1 | 0,51 | AllplanAttributes - Positionsnummer_Text: U23
Fensteröffnung | H2 Ebene 0 | 1105Fen2005779469 | m² | 0 | Fensterarbeiten | Fensteröffnung | 0 | 0 | NEW | 1105Wa 0000003794 | 0 | RC 1 | 0,51 | AllplanAttributes - Positionsnummer_Text: U23
Türöffnung | H2 Ebene 0 | 1105Tür0000085513 | m² | 0 | Trockenbauarbeiten | Türöffnung | 0 | 0 | NEW | 1105Wa 0000004039 | 0 | RC 1 | 0,51 | AllplanAttributes - Türanschlag: DIN L; Positionsnummer_Text: U23
Fensteröffnung | H2 Ebene 0 | 1105Fen2005779304 | m² | 0 | Fensterarbeiten | Fensteröffnung | 0 | 0 | NEW | 1105Wa 0000003784 | 0 | RC 1 | 0,51 | AllplanAttributes - Positionsnummer_Text: U23
Fensteröffnung | H2 Ebene 0 | 1105Fen2005779386 | m² | 0 | Fensterarbeiten | Fensteröffnung | 0 | 0 | NEW | 1105Wa 0000003784 | 0 | RC 1 | 0,51 | AllplanAttributes - Positionsnummer_Text: U23
Fensteröffnung | H2 Ebene 0 | 1105Fen2005779468 | m² | 0 | Fensterarbeiten | Fensteröffnung | 0 | 0 | NEW | 1105Wa 0000003784 | 0 | RC 1 | 0,51 | AllplanAttributes - Positionsnummer_Text: U23
Türöffnung | H2 Ebene 0 | 1105Tür0000085511 | m² | 0 | Trockenbauarbeiten | Türöffnung | 0 | 0 | NEW | 1105Wa 0000004044 | 0 | RC 1 | 0,51 | AllplanAttributes - Türanschlag: DIN L; Positionsnummer_Text: U23
Fensteröffnung | H2 Ebene 0 | 1105Fen2005793479 | m² | 0 | Fensterarbeiten | Fensteröffnung | 0 | 0 |  | 1105Wa 0000005133 | 0 | RC 1 | 0,51 | AllplanAttributes - Positionsnummer_Text: U23
Fensteröffnung | H2 Ebene 0 | 1105Fen2005793561 | m² | 0 | Fensterarbeiten | Fensteröffnung | 0 | 0 |  | 1105Wa 0000005133 | 0 | RC 1 | 0,51 | AllplanAttributes - Positionsnummer_Text: U23
Fensteröffnung | H2 Ebene 0 | 1105Fen2005793643 | m² | 0 | Fensterarbeiten | Fensteröffnung | 0 | 0 |  | 1105Wa 0000005133 | 0 | RC 1 | 0,51 | AllplanAttributes - Positionsnummer_Text: U23
Türöffnung | H2 Ebene 0 | 1105Tür0000085822 | m² |  | Trockenbauarbeiten | Türöffnung |  | 0 | NEW | 1105Wa 0000005175 | 0 | RC 1 | 0,51 | AllplanAttributes - Codetext: Codetext; Türanschlag: DIN R; Positionsnummer_Text: U23; Pset_OpeningElementCommon - FireExit: no; Reference: Codetext
Fensteröffnung | H2 Ebene 0 | 1105Fen2005793478 | m³ | 0 | Fensterarbeiten | Fensteröffnung | 0 | 0 |  | 1105Wa 0000005124 | 0 | RC 1 | 0,51 | AllplanAttributes - Positionsnummer_Text: U23
Fensteröffnung | H2 Ebene 0 | 1105Fen2005793560 | m³ | 0 | Fensterarbeiten | Fensteröffnung | 0 | 0 |  | 1105Wa 0000005124 | 0 | RC 1 | 0,51 | AllplanAttributes - Positionsnummer_Text: U23
Fensteröffnung | H2 Ebene 0 | 1105Fen2005793642 | m³ | 0 | Fensterarbeiten | Fensteröffnung | 0 | 0 |  | 1105Wa 0000005124 | 0 | RC 1 | 0,51 | AllplanAttributes - Positionsnummer_Text: U23
Türöffnung | H2 Ebene 0 | 1105Tür0000085824 | m³ | 0 | Trockenbauarbeiten | Türöffnung | 0 | 0 | NEW | 1105Wa 0000005180 | 0 | RC 1 | 0,51 | AllplanAttributes - Türanschlag: DIN R; Positionsnummer_Text: U23
Fensteröffnung | H2 Ebene 0 | 1105Fen2005793477 | m³ | 0 | Fensterarbeiten | Fensteröffnung | 0 | 0 |  | 1105Wa 0000005115 | 0 | RC 1 | 0,51 | AllplanAttributes - Positionsnummer_Text: U23
Fensteröffnung | H2 Ebene 0 | 1105Fen2005793559 | m³ | 0 | Fensterarbeiten | Fensteröffnung | 0 | 0 |  | 1105Wa 0000005115 | 0 | RC 1 | 0,51 | AllplanAttributes - Positionsnummer_Text: U23
Fensteröffnung | H2 Ebene 0 | 1105Fen2005793641 | m³ | 0 | Fensterarbeiten | Fensteröffnung | 0 | 0 |  | 1105Wa 0000005115 | 0 | RC 1 | 0,51 | AllplanAttributes - Positionsnummer_Text: U23
Türöffnung | H2 Ebene 0 | 1105Tür0000085834 | m³ | 0 | Trockenbauarbeiten | Türöffnung | 0 | 0 | NEW | 1105Wa 0000005184 | 0 | RC 1 | 0,51 | AllplanAttributes - Türanschlag: DIN R; Positionsnummer_Text: U23
Fensteröffnung | H2 Ebene 0 | 1105Fen2005793476 | m² | 0 | Fensterarbeiten | Fensteröffnung | 0 | 0 |  | 1105Wa 0000005106 | 0 | RC 1 | 0,51 | AllplanAttributes - Positionsnummer_Text: U23
Fensteröffnung | H2 Ebene 0 | 1105Fen2005793558 | m² | 0 | Fensterarbeiten | Fensteröffnung | 0 | 0 |  | 1105Wa 0000005106 | 0 | RC 1 | 0,51 | AllplanAttributes - Positionsnummer_Text: U23
Fensteröffnung | H2 Ebene 0 | 1105Fen2005793640 | m² | 0 | Fensterarbeiten | Fensteröffnung | 0 | 0 |  | 1105Wa 0000005106 | 0 | RC 1 | 0,51 | AllplanAttributes - Positionsnummer_Text: U23
Türöffnung | H2 Ebene 0 | 1105Tür0000085826 | m² | 0 | Trockenbauarbeiten | Türöffnung | 0 | 0 | NEW | 1105Wa 0000005189 | 0 | RC 1 | 0,51 | AllplanAttributes - Türanschlag: DIN R; Positionsnummer_Text: U23
Fensteröffnung | H2 Ebene 0 | 1105Fen2005793475 | m² | 0 | Fensterarbeiten | Fensteröffnung | 0 | 0 | NEW | 1105Wa 0000005097 | 0 | RC 1 | 0,51 | AllplanAttributes - Positionsnummer_Text: U23
Fensteröffnung | H2 Ebene 0 | 1105Fen2005793557 | m² | 0 | Fensterarbeiten | Fensteröffnung | 0 | 0 | NEW | 1105Wa 0000005097 | 0 | RC 1 | 0,51 | AllplanAttributes - Positionsnummer_Text: U23
Fensteröffnung | H2 Ebene 0 | 1105Fen2005793639 | m² | 0 | Fensterarbeiten | Fensteröffnung | 0 | 0 | NEW | 1105Wa 0000005097 | 0 | RC 1 | 0,51 | AllplanAttributes - Positionsnummer_Text: U23
Türöffnung | H2 Ebene 0 | 1105Tür0000085828 | m² | 0 | Trockenbauarbeiten | Türöffnung | 0 | 0 | NEW | 1105Wa 0000005194 | 0 | RC 1 | 0,51 | AllplanAttributes - Türanschlag: DIN R; Positionsnummer_Text: U23
Fensteröffnung | H2 Ebene 0 | 1105Fen2005793474 | m² | 0 | Fensterarbeiten | Fensteröffnung | 0 | 0 | NEW | 1105Wa 0000005088 | 0 | RC 1 | 0,51 | AllplanAttributes - Positionsnummer_Text: U23
Fensteröffnung | H2 Ebene 0 | 1105Fen2005793556 | m² | 0 | Fensterarbeiten | Fensteröffnung | 0 | 0 | NEW | 1105Wa 0000005088 | 0 | RC 1 | 0,51 | AllplanAttributes - Positionsnummer_Text: U23
Fensteröffnung | H2 Ebene 0 | 1105Fen2005793638 | m² | 0 | Fensterarbeiten | Fensteröffnung | 0 | 0 | NEW | 1105Wa 0000005088 | 0 | RC 1 | 0,51 | AllplanAttributes - Positionsnummer_Text: U23
Türöffnung | H2 Ebene 0 | 1105Tür0000085830 | m² | 0 | Trockenbauarbeiten | Türöffnung | 0 | 0 | NEW | 1105Wa 0000005199 | 0 | RC 1 | 0,51 | AllplanAttributes - Türanschlag: DIN R; Positionsnummer_Text: U23
Fensteröffnung | H2 Ebene 0 | 1105Fen2005793473 | m² | 0 | Fensterarbeiten | Fensteröffnung | 0 | 0 | NEW | 1105Wa 0000005079 | 0 | RC 1 | 0,51 | AllplanAttributes - Positionsnummer_Text: U23
Fensteröffnung | H2 Ebene 0 | 1105Fen2005793555 | m² | 0 | Fensterarbeiten | Fensteröffnung | 0 | 0 | NEW | 1105Wa 0000005079 | 0 | RC 1 | 0,51 | AllplanAttributes - Positionsnummer_Text: U23
Fensteröffnung | H2 Ebene 0 | 1105Fen2005793637 | m² | 0 | Fensterarbeiten | Fensteröffnung | 0 | 0 | NEW | 1105Wa 0000005079 | 0 | RC 1 | 0,51 | AllplanAttributes - Positionsnummer_Text: U23
Türöffnung | H2 Ebene 0 | 1105Tür0000085832 | m² | 0 | Trockenbauarbeiten | Türöffnung | 0 | 0 | NEW | 1105Wa 0000005170 | 0 | RC 1 | 0,51 | AllplanAttributes - Türanschlag: DIN R; Positionsnummer_Text: U23
Fensteröffnung | H2 Ebene 0 | 1105Fen2005792516 | m² | 0 | Fensterarbeiten | Fensteröffnung | 0 | 0 |  | 1105Wa 0000180626 | 0 | RC 1 | 0,51 | AllplanAttributes - Positionsnummer_Text: U23
Fensteröffnung | H2 Ebene 0 | 1105Fen2005792608 | m² | 0 | Fensterarbeiten | Fensteröffnung | 0 | 0 |  | 1105Wa 0000180626 | 0 | RC 1 | 0,51 | AllplanAttributes - Positionsnummer_Text: U23
Fensteröffnung | H2 Ebene 0 | 1105Fen2005792690 | m² | 0 | Fensterarbeiten | Fensteröffnung | 0 | 0 |  | 1105Wa 0000180626 | 0 | RC 1 | 0,51 | AllplanAttributes - Positionsnummer_Text: U23
Türöffnung | H2 Ebene 0 | 1105Tür0000085630 | m² |  | Trockenbauarbeiten | Türöffnung |  | 0 | NEW | 1105Wa 0000005305 | 0 | RC 1 | 0,51 | AllplanAttributes - Codetext: Codetext; Türanschlag: DIN L; Positionsnummer_Text: U23; Pset_OpeningElementCommon - FireExit: no; Reference: Codetext
Fensteröffnung | H2 Ebene 0 | 1105Fen2005792515 | m³ | 0 | Fensterarbeiten | Fensteröffnung | 0 | 0 |  | 1105Wa 0000180627 | 0 | RC 1 | 0,51 | AllplanAttributes - Positionsnummer_Text: U23
Fensteröffnung | H2 Ebene 0 | 1105Fen2005792607 | m³ | 0 | Fensterarbeiten | Fensteröffnung | 0 | 0 |  | 1105Wa 0000180627 | 0 | RC 1 | 0,51 | AllplanAttributes - Positionsnummer_Text: U23
Fensteröffnung | H2 Ebene 0 | 1105Fen2005792689 | m³ | 0 | Fensterarbeiten | Fensteröffnung | 0 | 0 |  | 1105Wa 0000180627 | 0 | RC 1 | 0,51 | AllplanAttributes - Positionsnummer_Text: U23
Türöffnung | H2 Ebene 0 | 1105Tür0000085632 | m³ | 0 | Trockenbauarbeiten | Türöffnung | 0 | 0 | NEW | 1105Wa 0000005310 | 0 | RC 1 | 0,51 | AllplanAttributes - Türanschlag: DIN L; Positionsnummer_Text: U23
Fensteröffnung | H2 Ebene 0 | 1105Fen2005792514 | m³ | 0 | Fensterarbeiten | Fensteröffnung | 0 | 0 |  | 1105Wa 0000180628 | 0 | RC 1 | 0,51 | AllplanAttributes - Positionsnummer_Text: U23
Fensteröffnung | H2 Ebene 0 | 1105Fen2005792606 | m³ | 0 | Fensterarbeiten | Fensteröffnung | 0 | 0 |  | 1105Wa 0000180628 | 0 | RC 1 | 0,51 | AllplanAttributes - Positionsnummer_Text: U23
Fensteröffnung | H2 Ebene 0 | 1105Fen2005792688 | m³ | 0 | Fensterarbeiten | Fensteröffnung | 0 | 0 |  | 1105Wa 0000180628 | 0 | RC 1 | 0,51 | AllplanAttributes - Positionsnummer_Text: U23
Türöffnung | H2 Ebene 0 | 1105Tür0000085634 | m³ | 0 | Trockenbauarbeiten | Türöffnung | 0 | 0 | NEW | 1105Wa 0000005315 | 0 | RC 1 | 0,51 | AllplanAttributes - Türanschlag: DIN L; Positionsnummer_Text: U23
Fensteröffnung | H2 Ebene 0 | 1105Fen2005792513 | m³ | 0 | Fensterarbeiten | Fensteröffnung | 0 | 0 |  | 1105Wa 0000180629 | 0 | RC 1 | 0,51 | AllplanAttributes - Positionsnummer_Text: U23
Fensteröffnung | H2 Ebene 0 | 1105Fen2005792605 | m³ | 0 | Fensterarbeiten | Fensteröffnung | 0 | 0 |  | 1105Wa 0000180629 | 0 | RC 1 | 0,51 | AllplanAttributes - Positionsnummer_Text: U23
Fensteröffnung | H2 Ebene 0 | 1105Fen2005792687 | m³ | 0 | Fensterarbeiten | Fensteröffnung | 0 | 0 |  | 1105Wa 0000180629 | 0 | RC 1 | 0,51 | AllplanAttributes - Positionsnummer_Text: U23
Türöffnung | H2 Ebene 0 | 1105Tür0000085636 | m³ | 0 | Trockenbauarbeiten | Türöffnung | 0 | 0 | NEW | 1105Wa 0000005320 | 0 | RC 1 | 0,51 | AllplanAttributes - Türanschlag: DIN L; Positionsnummer_Text: U23
Fensteröffnung | H2 Ebene 0 | 1105Fen2005792512 | m² | 0 | Fensterarbeiten | Fensteröffnung | 0 | 0 | NEW | 1105Wa 0000180630 | 0 | RC 1 | 0,51 | AllplanAttributes - Positionsnummer_Text: U23
Fensteröffnung | H2 Ebene 0 | 1105Fen2005792604 | m² | 0 | Fensterarbeiten | Fensteröffnung | 0 | 0 | NEW | 1105Wa 0000180630 | 0 | RC 1 | 0,51 | AllplanAttributes - Positionsnummer_Text: U23
Fensteröffnung | H2 Ebene 0 | 1105Fen2005792686 | m² | 0 | Fensterarbeiten | Fensteröffnung | 0 | 0 | NEW | 1105Wa 0000180630 | 0 | RC 1 | 0,51 | AllplanAttributes - Positionsnummer_Text: U23
Türöffnung | H2 Ebene 0 | 1105Tür0000085638 | m² | 0 | Trockenbauarbeiten | Türöffnung | 0 | 0 | NEW | 1105Wa 0000005325 | 0 | RC 1 | 0,51 | AllplanAttributes - Türanschlag: DIN L; Positionsnummer_Text: U23
Fensteröffnung | H2 Ebene 0 | 1105Fen2005792511 | m² | 0 | Fensterarbeiten | Fensteröffnung | 0 | 0 | NEW | 1105Wa 0000180631 | 0 | RC 1 | 0,51 | AllplanAttributes - Positionsnummer_Text: U23
Fensteröffnung | H2 Ebene 0 | 1105Fen2005792603 | m² | 0 | Fensterarbeiten | Fensteröffnung | 0 | 0 | NEW | 1105Wa 0000180631 | 0 | RC 1 | 0,51 | AllplanAttributes - Positionsnummer_Text: U23
Fensteröffnung | H2 Ebene 0 | 1105Fen2005792685 | m² | 0 | Fensterarbeiten | Fensteröffnung | 0 | 0 | NEW | 1105Wa 0000180631 | 0 | RC 1 | 0,51 | AllplanAttributes - Positionsnummer_Text: U23
Türöffnung | H2 Ebene 0 | 1105Tür0000085640 | m² | 0 | Trockenbauarbeiten | Türöffnung | 0 | 0 | NEW | 1105Wa 0000005330 | 0 | RC 1 | 0,51 | AllplanAttributes - Türanschlag: DIN L; Positionsnummer_Text: U23
Fensteröffnung | H2 Ebene 0 | 1105Fen2005792510 | m² | 0 | Fensterarbeiten | Fensteröffnung | 0 | 0 | NEW | 1105Wa 0000180632 | 0 | RC 1 | 0,51 | AllplanAttributes - Positionsnummer_Text: U23
Fensteröffnung | H2 Ebene 0 | 1105Fen2005792602 | m² | 0 | Fensterarbeiten | Fensteröffnung | 0 | 0 | NEW | 1105Wa 0000180632 | 0 | RC 1 | 0,51 | AllplanAttributes - Positionsnummer_Text: U23
Fensteröffnung | H2 Ebene 0 | 1105Fen2005792684 | m² | 0 | Fensterarbeiten | Fensteröffnung | 0 | 0 | NEW | 1105Wa 0000180632 | 0 | RC 1 | 0,51 | AllplanAttributes - Positionsnummer_Text: U23
Türöffnung | H2 Ebene 0 | 1105Tür0000085642 | m² | 0 | Trockenbauarbeiten | Türöffnung | 0 | 0 | NEW | 1105Wa 0000005335 | 0 | RC 1 | 0,51 | AllplanAttributes - Türanschlag: DIN L; Positionsnummer_Text: U23
Fensteröffnung | H2 Ebene 0 | 1105Fen2005792509 | m² | 0 | Fensterarbeiten | Fensteröffnung | 0 |  | NEW | 1105Wa 0811580073 | AllplanAttributes - Positionsnummer_Text: U23
Fensteröffnung | H2 Ebene 0 | 1105Fen2005792601 | m² | 0 | Fensterarbeiten | Fensteröffnung | 0 |  | NEW | 1105Wa 0811580073 | AllplanAttributes - Positionsnummer_Text: U23
Fensteröffnung | H2 Ebene 0 | 1105Fen2005792683 | m² | 0 | Fensterarbeiten | Fensteröffnung | 0 |  | NEW | 1105Wa 0811580073 | AllplanAttributes - Positionsnummer_Text: U23
Türöffnung | H2 Ebene 0 | 1105Tür0811581453 | m² | 0 | Trockenbauarbeiten | Türöffnung | 0 |  | NEW | 1105Wa 0811581132 | AllplanAttributes - Türanschlag: DIN L; Positionsnummer_Text: U23
Fensteröffnung | H2 Ebene 0 | 1105Fen0000053688 | m² |  | Fensterarbeiten | Fensteröffnung |  | 0 |  | 1105Wa 0000004689 | 0 | RC 1 | 0,51 | AllplanAttributes - Positionsnummer_Text: U23
Fensteröffnung | H2 Ebene 0 | 1105Fen0000053689 | m³ | 0 | Fensterarbeiten | Fensteröffnung | 0 | 0 |  | 1105Wa 0000004693 | 0 | RC 1 | 0,51 | AllplanAttributes - Positionsnummer_Text: U23
Fensteröffnung | H2 Ebene 0 | 1105Fen0000053690 | m³ | 0 | Fensterarbeiten | Fensteröffnung | 0 | 0 |  | 1105Wa 0000004697 | 0 | RC 1 | 0,51 | AllplanAttributes - Positionsnummer_Text: U23
Fensteröffnung | H2 Ebene 0 | 1105Fen0000053691 | m² | 0 | Fensterarbeiten | Fensteröffnung | 0 | 0 |  | 1105Wa 0000004701 | 0 | RC 1 | 0,51 | AllplanAttributes - Positionsnummer_Text: U23
Fensteröffnung | H2 Ebene 0 | 1105Fen0000053692 | m² | 0 | Fensterarbeiten | Fensteröffnung | 0 | 0 | NEW | 1105Wa 0000004705 | 0 | RC 1 | 0,51 | AllplanAttributes - Positionsnummer_Text: U23
Fensteröffnung | H2 Ebene 0 | 1105Fen0000053693 | m² | 0 | Fensterarbeiten | Fensteröffnung | 0 | 0 | NEW | 1105Wa 0000004709 | 0 | RC 1 | 0,51 | AllplanAttributes - Positionsnummer_Text: U23
Fensteröffnung | H2 Ebene 0 | 1105Fen0000053694 | m² | 0 | Fensterarbeiten | Fensteröffnung | 0 | 0 | NEW | 1105Wa 0000004713 | 0 | RC 1 | 0,51 | AllplanAttributes - Positionsnummer_Text: U23
Fensteröffnung | H2 Ebene 0 | 1105Fen0811557430 | m² |  | Wärmedämm-Verbundsysteme | Fensteröffnung |  | 0 | NEW | 1105Wa 0811557440 | 0 | RC 1 | 0,51 | AllplanAttributes - Material: Fensterelement; Tragendes Bauteil: no; Brandabschnittsdefinierendes Bauteil: no; Positionsnummer_Text: U23
Fensteröffnung | H2 Ebene 0 | 1105Fen0811557423 | m² |  | Wärmedämm-Verbundsysteme | Fensteröffnung |  | 0 | NEW | 1105Wa 0811557440 | 0 | RC 1 | 0,51 | AllplanAttributes - Material: Fensterelement; Tragendes Bauteil: no; Brandabschnittsdefinierendes Bauteil: no; Positionsnummer_Text: U23
Fensteröffnung | H2 Ebene 0 | 1105Fen0811557431 | m³ | 0 | Wärmedämm-Verbundsysteme | Fensteröffnung | 0 | 0 | NEW | 1105Wa 0811557437 | 0 | RC 1 | 0,51 | AllplanAttributes - Material: Fensterelement; Außenliegend: yes; Positionsnummer_Text: U23
Fensteröffnung | H2 Ebene 0 | 1105Fen0811557429 | m³ | 0 | Wärmedämm-Verbundsysteme | Fensteröffnung | 0 | 0 | NEW | 1105Wa 0811557437 | 0 | RC 1 | 0,51 | AllplanAttributes - Material: Fensterelement; Außenliegend: yes; Positionsnummer_Text: U23
Fensteröffnung | H2 Ebene 0 | 1105Fen0811557428 | m³ | 0 | Wärmedämm-Verbundsysteme | Fensteröffnung | 0 | 0 | NEW | 1105Wa 0811557436 | 0 | RC 1 | 0,51 | AllplanAttributes - Positionsnummer_Text: U23
Fensteröffnung | H2 Ebene 0 | 1105Fen0811557422 | m³ | 0 | Wärmedämm-Verbundsysteme | Fensteröffnung | 0 | 0 | NEW | 1105Wa 0811557436 | 0 | RC 1 | 0,51 | AllplanAttributes - Positionsnummer_Text: U23
Fensteröffnung | H2 Ebene 0 | 1105Fen0811557421 | m² | 0 | Wärmedämm-Verbundsysteme | Fensteröffnung | 0 | 0 | NEW | 1105Wa 0811557435 | 0 | RC 1 | 0,51 | AllplanAttributes - Positionsnummer_Text: U23
Fensteröffnung | H2 Ebene 0 | 1105Fen0811557427 | m² | 0 | Wärmedämm-Verbundsysteme | Fensteröffnung | 0 | 0 | NEW | 1105Wa 0811557435 | 0 | RC 1 | 0,51 | AllplanAttributes - Positionsnummer_Text: U23
Fensteröffnung | H2 Ebene 0 | 1105Fen0811557426 | m² | 0 | Wärmedämm-Verbundsysteme | Fensteröffnung | 0 | 0 | NEW | 1105Wa 0811557434 | 0 | RC 1 | 0,51 | AllplanAttributes - Positionsnummer_Text: U23
Fensteröffnung | H2 Ebene 0 | 1105Fen0811557420 | m² | 0 | Wärmedämm-Verbundsysteme | Fensteröffnung | 0 | 0 | NEW | 1105Wa 0811557434 | 0 | RC 1 | 0,51 | AllplanAttributes - Positionsnummer_Text: U23
Fensteröffnung | H2 Ebene 0 | 1105Fen0811557419 | m² | 0 | Wärmedämm-Verbundsysteme | Fensteröffnung | 0 | 0 | NEW | 1105Wa 0811557433 | 0 | RC 1 | 0,51 | AllplanAttributes - Positionsnummer_Text: U23
Fensteröffnung | H2 Ebene 0 | 1105Fen0811557425 | m² | 0 | Wärmedämm-Verbundsysteme | Fensteröffnung | 0 | 0 | NEW | 1105Wa 0811557433 | 0 | RC 1 | 0,51 | AllplanAttributes - Positionsnummer_Text: U23
Fensteröffnung | H2 Ebene 0 | 1105Fen0811557424 | m² | 0 | Wärmedämm-Verbundsysteme | Fensteröffnung | 0 | 0 | NEW | 1105Wa 0811557432 | 0 | RC 1 | 0,51 | AllplanAttributes - Positionsnummer_Text: U23
Fensteröffnung | H2 Ebene 0 | 1105Fen0811557418 | m² | 0 | Wärmedämm-Verbundsysteme | Fensteröffnung | 0 | 0 | NEW | 1105Wa 0811557432 | 0 | RC 1 | 0,51 | AllplanAttributes - Positionsnummer_Text: U23
Fensteröffnung | H2 Ebene 0 | 1105Fen0000039914 | m² |  | Wärmedämm-Verbundsysteme | Fensteröffnung |  | 7.5 | NEW | 1105Wa 0000000706 | 0 | RC 1 | 0,51 | AllplanAttributes - Material: Fensterelement; Tragendes Bauteil: no; Brandabschnittsdefinierendes Bauteil: no; Positionsnummer_Text: U23
Fensteröffnung | H2 Ebene 0 | 1105Fen0000039956 | m² |  | Wärmedämm-Verbundsysteme | Fensteröffnung |  | 7.5 | NEW | 1105Wa 0000000706 | 0 | RC 1 | 0,51 | AllplanAttributes - Material: Fensterelement; Tragendes Bauteil: no; Brandabschnittsdefinierendes Bauteil: no; Positionsnummer_Text: U23
Fensteröffnung | H2 Ebene 0 | 1105Fen0000039915 | m³ | 0 | Wärmedämm-Verbundsysteme | Fensteröffnung | 0 | 7.5 | NEW | 1105Wa 0000000710 | 0 | RC 1 | 0,51 | AllplanAttributes - Material: Fensterelement; Außenliegend: yes; Positionsnummer_Text: U23
Fensteröffnung | H2 Ebene 0 | 1105Fen0000039957 | m³ | 0 | Wärmedämm-Verbundsysteme | Fensteröffnung | 0 | 7.5 | NEW | 1105Wa 0000000710 | 0 | RC 1 | 0,51 | AllplanAttributes - Material: Fensterelement; Außenliegend: yes; Positionsnummer_Text: U23
Fensteröffnung | H2 Ebene 0 | 1105Fen0000039916 | m³ | 0 | Wärmedämm-Verbundsysteme | Fensteröffnung | 0 | 7.5 | NEW | 1105Wa 0000000730 | 0 | RC 1 | 0,51 | AllplanAttributes - Positionsnummer_Text: U23
Fensteröffnung | H2 Ebene 0 | 1105Fen0000039958 | m³ | 0 | Wärmedämm-Verbundsysteme | Fensteröffnung | 0 | 7.5 | NEW | 1105Wa 0000000730 | 0 | RC 1 | 0,51 | AllplanAttributes - Positionsnummer_Text: U23
Fensteröffnung | H2 Ebene 0 | 1105Fen0000039917 | m² | 0 | Wärmedämm-Verbundsysteme | Fensteröffnung | 0 | 7.5 | NEW | 1105Wa 0000000726 | 0 | RC 1 | 0,51 | AllplanAttributes - Positionsnummer_Text: U23
Fensteröffnung | H2 Ebene 0 | 1105Fen0000039959 | m² | 0 | Wärmedämm-Verbundsysteme | Fensteröffnung | 0 | 7.5 | NEW | 1105Wa 0000000726 | 0 | RC 1 | 0,51 | AllplanAttributes - Positionsnummer_Text: U23
Fensteröffnung | H2 Ebene 0 | 1105Fen0000039918 | m² | 0 | Wärmedämm-Verbundsysteme | Fensteröffnung | 0 | 7.5 | NEW | 1105Wa 0000000722 | 0 | RC 1 | 0,51 | AllplanAttributes - Positionsnummer_Text: U23
Fensteröffnung | H2 Ebene 0 | 1105Fen0000039960 | m² | 0 | Wärmedämm-Verbundsysteme | Fensteröffnung | 0 | 7.5 | NEW | 1105Wa 0000000722 | 0 | RC 1 | 0,51 | AllplanAttributes - Positionsnummer_Text: U23
Fensteröffnung | H2 Ebene 0 | 1105Fen0000039919 | m² | 0 | Wärmedämm-Verbundsysteme | Fensteröffnung | 0 | 7.5 | NEW | 1105Wa 0000000718 | 0 | RC 1 | 0,51 | AllplanAttributes - Positionsnummer_Text: U23
Fensteröffnung | H2 Ebene 0 | 1105Fen0000039961 | m² | 0 | Wärmedämm-Verbundsysteme | Fensteröffnung | 0 | 7.5 | NEW | 1105Wa 0000000718 | 0 | RC 1 | 0,51 | AllplanAttributes - Positionsnummer_Text: U23
Fensteröffnung | H2 Ebene 0 | 1105Fen0000039920 | m² | 0 | Wärmedämm-Verbundsysteme | Fensteröffnung | 0 | 7.5 | NEW | 1105Wa 0000000714 | 0 | RC 1 | 0,51 | AllplanAttributes - Positionsnummer_Text: U23
Fensteröffnung | H2 Ebene 0 | 1105Fen0000039962 | m² | 0 | Wärmedämm-Verbundsysteme | Fensteröffnung | 0 | 7.5 | NEW | 1105Wa 0000000714 | 0 | RC 1 | 0,51 | AllplanAttributes - Positionsnummer_Text: U23
Fensteröffnung | H2 Ebene 0 | 1105Fen0000040010 | m² |  | Wärmedämm-Verbundsysteme | Fensteröffnung |  | 7.5 | NEW | 1105Wa 0000000762 | 0 | RC 1 | 0,51 | AllplanAttributes - Material: Fensterelement; Tragendes Bauteil: no; Brandabschnittsdefinierendes Bauteil: no; Positionsnummer_Text: U23
Fensteröffnung | H2 Ebene 0 | 1105Fen0000040052 | m² |  | Wärmedämm-Verbundsysteme | Fensteröffnung |  | 7.5 | NEW | 1105Wa 0000000762 | 0 | RC 1 | 0,51 | AllplanAttributes - Material: Fensterelement; Tragendes Bauteil: no; Brandabschnittsdefinierendes Bauteil: no; Positionsnummer_Text: U23
Fensteröffnung | H2 Ebene 0 | 1105Fen0000040011 | m³ | 0 | Wärmedämm-Verbundsysteme | Fensteröffnung | 0 | 7.5 | NEW | 1105Wa 0000000758 | 0 | RC 1 | 0,51 | AllplanAttributes - Material: Fensterelement; Außenliegend: yes; Positionsnummer_Text: U23
Fensteröffnung | H2 Ebene 0 | 1105Fen0000040053 | m³ | 0 | Wärmedämm-Verbundsysteme | Fensteröffnung | 0 | 7.5 | NEW | 1105Wa 0000000758 | 0 | RC 1 | 0,51 | AllplanAttributes - Material: Fensterelement; Außenliegend: yes; Positionsnummer_Text: U23
Fensteröffnung | H2 Ebene 0 | 1105Fen0000040054 | m³ | 0 | Wärmedämm-Verbundsysteme | Fensteröffnung | 0 | 7.5 | NEW | 1105Wa 0000000738 | 0 | RC 1 | 0,51 | AllplanAttributes - Positionsnummer_Text: U23
Fensteröffnung | H2 Ebene 0 | 1105Fen0000040012 | m³ | 0 | Wärmedämm-Verbundsysteme | Fensteröffnung | 0 | 7.5 | NEW | 1105Wa 0000000738 | 0 | RC 1 | 0,51 | AllplanAttributes - Positionsnummer_Text: U23
Fensteröffnung | H2 Ebene 0 | 1105Fen0000040013 | m² | 0 | Wärmedämm-Verbundsysteme | Fensteröffnung | 0 | 7.5 | NEW | 1105Wa 0000000742 | 0 | RC 1 | 0,51 | AllplanAttributes - Positionsnummer_Text: U23
Fensteröffnung | H2 Ebene 0 | 1105Fen0000040055 | m² | 0 | Wärmedämm-Verbundsysteme | Fensteröffnung | 0 | 7.5 | NEW | 1105Wa 0000000742 | 0 | RC 1 | 0,51 | AllplanAttributes - Positionsnummer_Text: U23
Fensteröffnung | H2 Ebene 0 | 1105Fen0000040056 | m² | 0 | Wärmedämm-Verbundsysteme | Fensteröffnung | 0 | 7.5 | NEW | 1105Wa 0000000746 | 0 | RC 1 | 0,51 | AllplanAttributes - Positionsnummer_Text: U23
Fensteröffnung | H2 Ebene 0 | 1105Fen0000040014 | m² | 0 | Wärmedämm-Verbundsysteme | Fensteröffnung | 0 | 7.5 | NEW | 1105Wa 0000000746 | 0 | RC 1 | 0,51 | AllplanAttributes - Positionsnummer_Text: U23
Fensteröffnung | H2 Ebene 0 | 1105Fen0000040057 | m² | 0 | Wärmedämm-Verbundsysteme | Fensteröffnung | 0 | 7.5 | NEW | 1105Wa 0000000750 | 0 | RC 1 | 0,51 | AllplanAttributes - Positionsnummer_Text: U23
Fensteröffnung | H2 Ebene 0 | 1105Fen0000040015 | m² | 0 | Wärmedämm-Verbundsysteme | Fensteröffnung | 0 | 7.5 | NEW | 1105Wa 0000000750 | 0 | RC 1 | 0,51 | AllplanAttributes - Positionsnummer_Text: U23
Fensteröffnung | H2 Ebene 0 | 1105Fen0000040016 | m² | 0 | Wärmedämm-Verbundsysteme | Fensteröffnung | 0 | 7.5 | NEW | 1105Wa 0000000754 | 0 | RC 1 | 0,51 | AllplanAttributes - Positionsnummer_Text: U23
Fensteröffnung | H2 Ebene 0 | 1105Fen0000040058 | m² | 0 | Wärmedämm-Verbundsysteme | Fensteröffnung | 0 | 7.5 | NEW | 1105Wa 0000000754 | 0 | RC 1 | 0,51 | AllplanAttributes - Positionsnummer_Text: U23
Fensteröffnung | H2 Ebene 0 | 1105Fen0000046637 | m² |  | Wärmedämm-Verbundsysteme | Fensteröffnung |  | 0 | NEW | 1105Wa 0000000962 | 0 | RC 1 | 0,51 | AllplanAttributes - Material: Fensterelement; Tragendes Bauteil: no; Brandabschnittsdefinierendes Bauteil: no; U-Wert: 0.9; Positionsnummer_Text: U23
Fensteröffnung | H2 Ebene 0 | 1105Fen0000046469 | m² |  | Wärmedämm-Verbundsysteme | Fensteröffnung |  | 0 | NEW | 1105Wa 0000000962 | 0 | RC 1 | 0,51 | AllplanAttributes - Material: Fensterelement; Tragendes Bauteil: no; Brandabschnittsdefinierendes Bauteil: no; U-Wert: 0.9; Positionsnummer_Text: U23
Fensteröffnung | H2 Ebene 0 | 1105Fen0000046470 | m³ | 0 | Wärmedämm-Verbundsysteme | Fensteröffnung | 0 | 0 | NEW | 1105Wa 0000000958 | 0 | RC 1 | 0,51 | AllplanAttributes - Material: Fensterelement; Außenliegend: yes; U-Wert: 0.9; Positionsnummer_Text: U23
Fensteröffnung | H2 Ebene 0 | 1105Fen0000046638 | m³ | 0 | Wärmedämm-Verbundsysteme | Fensteröffnung | 0 | 0 | NEW | 1105Wa 0000000958 | 0 | RC 1 | 0,51 | AllplanAttributes - Material: Fensterelement; Außenliegend: yes; U-Wert: 0.9; Positionsnummer_Text: U23
Fensteröffnung | H2 Ebene 0 | 1105Fen0000046639 | m³ | 0 | Wärmedämm-Verbundsysteme | Fensteröffnung | 0 | 0 | NEW | 1105Wa 0000000938 | 0 | RC 1 | 0,51 | AllplanAttributes - U-Wert: 0.9; Positionsnummer_Text: U23
Fensteröffnung | H2 Ebene 0 | 1105Fen0000046471 | m³ | 0 | Wärmedämm-Verbundsysteme | Fensteröffnung | 0 | 0 | NEW | 1105Wa 0000000938 | 0 | RC 1 | 0,51 | AllplanAttributes - U-Wert: 0.9; Positionsnummer_Text: U23
Fensteröffnung | H2 Ebene 0 | 1105Fen0000046472 | m² | 0 | Wärmedämm-Verbundsysteme | Fensteröffnung | 0 | 0 | NEW | 1105Wa 0000000942 | 0 | RC 1 | 0,51 | AllplanAttributes - U-Wert: 0.9; Positionsnummer_Text: U23
Fensteröffnung | H2 Ebene 0 | 1105Fen0000046640 | m² | 0 | Wärmedämm-Verbundsysteme | Fensteröffnung | 0 | 0 | NEW | 1105Wa 0000000942 | 0 | RC 1 | 0,51 | AllplanAttributes - U-Wert: 0.9; Positionsnummer_Text: U23
Fensteröffnung | H2 Ebene 0 | 1105Fen0000046641 | m² | 0 | Wärmedämm-Verbundsysteme | Fensteröffnung | 0 | 0 | NEW | 1105Wa 0000000946 | 0 | RC 1 | 0,51 | AllplanAttributes - U-Wert: 0.9; Positionsnummer_Text: U23
Fensteröffnung | H2 Ebene 0 | 1105Fen0000046473 | m² | 0 | Wärmedämm-Verbundsysteme | Fensteröffnung | 0 | 0 | NEW | 1105Wa 0000000946 | 0 | RC 1 | 0,51 | AllplanAttributes - U-Wert: 0.9; Positionsnummer_Text: U23
Fensteröffnung | H2 Ebene 0 | 1105Fen0000046642 | m² | 0 | Wärmedämm-Verbundsysteme | Fensteröffnung | 0 | 0 | NEW | 1105Wa 0000000950 | 0 | RC 1 | 0,51 | AllplanAttributes - U-Wert: 0.9; Positionsnummer_Text: U23
Fensteröffnung | H2 Ebene 0 | 1105Fen0000046474 | m² | 0 | Wärmedämm-Verbundsysteme | Fensteröffnung | 0 | 0 | NEW | 1105Wa 0000000950 | 0 | RC 1 | 0,51 | AllplanAttributes - U-Wert: 0.9; Positionsnummer_Text: U23
Fensteröffnung | H2 Ebene 0 | 1105Fen0000046475 | m² | 0 | Wärmedämm-Verbundsysteme | Fensteröffnung | 0 | 0 | NEW | 1105Wa 0000000954 | 0 | RC 1 | 0,51 | AllplanAttributes - U-Wert: 0.9; Positionsnummer_Text: U23
Fensteröffnung | H2 Ebene 0 | 1105Fen0000046643 | m² | 0 | Wärmedämm-Verbundsysteme | Fensteröffnung | 0 | 0 | NEW | 1105Wa 0000000954 | 0 | RC 1 | 0,51 | AllplanAttributes - U-Wert: 0.9; Positionsnummer_Text: U23
Fensteröffnung | H2 Ebene 0 | 1105Fen0000046511 | m² |  | Wärmedämm-Verbundsysteme | Fensteröffnung |  | 0 | NEW | 1105Wa 0000000910 | 0 | RC 1 | 0,51 | AllplanAttributes - Material: Fensterelement; Tragendes Bauteil: no; Brandabschnittsdefinierendes Bauteil: no; U-Wert: 0.9; Positionsnummer_Text: U23
Fensteröffnung | H2 Ebene 0 | 1105Fen0000046679 | m² |  | Wärmedämm-Verbundsysteme | Fensteröffnung |  | 0 | NEW | 1105Wa 0000000910 | 0 | RC 1 | 0,51 | AllplanAttributes - Material: Fensterelement; Tragendes Bauteil: no; Brandabschnittsdefinierendes Bauteil: no; U-Wert: 0.9; Positionsnummer_Text: U23
Fensteröffnung | H2 Ebene 0 | 1105Fen0000046512 | m³ | 0 | Wärmedämm-Verbundsysteme | Fensteröffnung | 0 | 0 | NEW | 1105Wa 0000000914 | 0 | RC 1 | 0,51 | AllplanAttributes - Material: Fensterelement; Außenliegend: yes; U-Wert: 0.9; Positionsnummer_Text: U23
Fensteröffnung | H2 Ebene 0 | 1105Fen0000046680 | m³ | 0 | Wärmedämm-Verbundsysteme | Fensteröffnung | 0 | 0 | NEW | 1105Wa 0000000914 | 0 | RC 1 | 0,51 | AllplanAttributes - Material: Fensterelement; Außenliegend: yes; U-Wert: 0.9; Positionsnummer_Text: U23
Fensteröffnung | H2 Ebene 0 | 1105Fen0000046513 | m³ | 0 | Wärmedämm-Verbundsysteme | Fensteröffnung | 0 | 0 | NEW | 1105Wa 0000000934 | 0 | RC 1 | 0,51 | AllplanAttributes - U-Wert: 0.9; Positionsnummer_Text: U23
Fensteröffnung | H2 Ebene 0 | 1105Fen0000046681 | m³ | 0 | Wärmedämm-Verbundsysteme | Fensteröffnung | 0 | 0 | NEW | 1105Wa 0000000934 | 0 | RC 1 | 0,51 | AllplanAttributes - U-Wert: 0.9; Positionsnummer_Text: U23
Fensteröffnung | H2 Ebene 0 | 1105Fen0000046514 | m² | 0 | Wärmedämm-Verbundsysteme | Fensteröffnung | 0 | 0 | NEW | 1105Wa 0000000930 | 0 | RC 1 | 0,51 | AllplanAttributes - U-Wert: 0.9; Positionsnummer_Text: U23
Fensteröffnung | H2 Ebene 0 | 1105Fen0000046682 | m² | 0 | Wärmedämm-Verbundsysteme | Fensteröffnung | 0 | 0 | NEW | 1105Wa 0000000930 | 0 | RC 1 | 0,51 | AllplanAttributes - U-Wert: 0.9; Positionsnummer_Text: U23
Fensteröffnung | H2 Ebene 0 | 1105Fen0000046515 | m² | 0 | Wärmedämm-Verbundsysteme | Fensteröffnung | 0 | 0 | NEW | 1105Wa 0000000926 | 0 | RC 1 | 0,51 | AllplanAttributes - U-Wert: 0.9; Positionsnummer_Text: U23
Fensteröffnung | H2 Ebene 0 | 1105Fen0000046683 | m² | 0 | Wärmedämm-Verbundsysteme | Fensteröffnung | 0 | 0 | NEW | 1105Wa 0000000926 | 0 | RC 1 | 0,51 | AllplanAttributes - U-Wert: 0.9; Positionsnummer_Text: U23
Fensteröffnung | H2 Ebene 0 | 1105Fen0000046516 | m² | 0 | Wärmedämm-Verbundsysteme | Fensteröffnung | 0 | 0 | NEW | 1105Wa 0000000922 | 0 | RC 1 | 0,51 | AllplanAttributes - U-Wert: 0.9; Positionsnummer_Text: U23
Fensteröffnung | H2 Ebene 0 | 1105Fen0000046684 | m² | 0 | Wärmedämm-Verbundsysteme | Fensteröffnung | 0 | 0 | NEW | 1105Wa 0000000922 | 0 | RC 1 | 0,51 | AllplanAttributes - U-Wert: 0.9; Positionsnummer_Text: U23
Fensteröffnung | H2 Ebene 0 | 1105Fen0000046517 | m² | 0 | Wärmedämm-Verbundsysteme | Fensteröffnung | 0 | 0 | NEW | 1105Wa 0000000918 | 0 | RC 1 | 0,51 | AllplanAttributes - U-Wert: 0.9; Positionsnummer_Text: U23
Fensteröffnung | H2 Ebene 0 | 1105Fen0000046685 | m² | 0 | Wärmedämm-Verbundsysteme | Fensteröffnung | 0 | 0 | NEW | 1105Wa 0000000918 | 0 | RC 1 | 0,51 | AllplanAttributes - U-Wert: 0.9; Positionsnummer_Text: U23
Fensteröffnung | H2 Ebene 0 | 1105Fen0000061270 | m² |  | Fensterarbeiten | Fensteröffnung |  | 0 |  | 1105Wa 0000003057 | 0 | RC 1 | 0,51 | AllplanAttributes - Positionsnummer_Text: U23
Fensteröffnung | H2 Ebene 0 | 1105Fen0000061268 | m³ | 0 | Fensterarbeiten | Fensteröffnung | 0 | 0 |  | 1105Wa 0000003053 | 0 | RC 1 | 0,51 | AllplanAttributes - Positionsnummer_Text: U23
Fensteröffnung | H2 Ebene 0 | 1105Fen0000061266 | m³ | 0 | Fensterarbeiten | Fensteröffnung | 0 | 0 |  | 1105Wa 0000003049 | 0 | RC 1 | 0,51 | AllplanAttributes - Positionsnummer_Text: U23
Fensteröffnung | H2 Ebene 0 | 1105Fen0000061264 | m² | 0 | Fensterarbeiten | Fensteröffnung | 0 | 0 |  | 1105Wa 0000003045 | 0 | RC 1 | 0,51 | AllplanAttributes - Positionsnummer_Text: U23
Fensteröffnung | H2 Ebene 0 | 1105Fen0000061262 | m² | 0 | Fensterarbeiten | Fensteröffnung | 0 | 0 | NEW | 1105Wa 0000003041 | 0 | RC 1 | 0,51 | AllplanAttributes - Positionsnummer_Text: U23
Fensteröffnung | H2 Ebene 0 | 1105Fen0000061260 | m² | 0 | Fensterarbeiten | Fensteröffnung | 0 | 0 | NEW | 1105Wa 0000003037 | 0 | RC 1 | 0,51 | AllplanAttributes - Positionsnummer_Text: U23
Fensteröffnung | H2 Ebene 0 | 1105Fen0000061258 | m² | 0 | Fensterarbeiten | Fensteröffnung | 0 | 0 | NEW | 1105Wa 0000003033 | 0 | RC 1 | 0,51 | AllplanAttributes - Positionsnummer_Text: U23
Türöffnung | H2 Ebene 0 | 1105Tür0811632320 | m² |  | Trockenbauarbeiten | Türöffnung |  |  |  | 1105Wa 0811632325 | 0 | RC 1 | 0,51 | AllplanAttributes - Türanschlag: DIN L; Positionsnummer_Text: U23
Türöffnung | H2 Ebene 0 | 1105Tür0811632319 | m³ | 0 | Trockenbauarbeiten | Türöffnung | 0 |  | NEW | 1105Wa 0811632331 | AllplanAttributes - Türanschlag: DIN L; Positionsnummer_Text: U23
Türöffnung | H2 Ebene 0 | 1105Tür0811632318 | m³ | 0 | Trockenbauarbeiten | Türöffnung | 0 |  | NEW | 1105Wa 0811632330 | AllplanAttributes - Türanschlag: DIN L; Positionsnummer_Text: U23
Türöffnung | H2 Ebene 0 | 1105Tür0811632317 | m² | 0 | Trockenbauarbeiten | Türöffnung | 0 |  | NEW | 1105Wa 0811632329 | AllplanAttributes - Türanschlag: DIN L; Positionsnummer_Text: U23
Türöffnung | H2 Ebene 0 | 1105Tür0811632316 | m² | 0 | Trockenbauarbeiten | Türöffnung | 0 |  | NEW | 1105Wa 0811632328 | AllplanAttributes - Türanschlag: DIN L; Positionsnummer_Text: U23
Türöffnung | H2 Ebene 0 | 1105Tür0811632315 | m² | 0 | Trockenbauarbeiten | Türöffnung | 0 |  | NEW | 1105Wa 0811632327 | AllplanAttributes - Türanschlag: DIN L; Positionsnummer_Text: U23
Türöffnung | H2 Ebene 0 | 1105Tür0811632314 | m² | 0 | Trockenbauarbeiten | Türöffnung | 0 |  | NEW | 1105Wa 0811632326 | AllplanAttributes - ash D_Detailverweis: FSE1; ash D_Plannummer: D786; Bezeichnung: Türöffnung; Türanschlag: DIN L; Positionsnummer_Text: U23
Fensteröffnung | H2 Ebene 0 | 1105Fen0000043620 | m² |  | Wärmedämm-Verbundsysteme | Fensteröffnung |  | 0 | NEW | 1105Wa 0000001193 | 0 | RC 1 | 0,51 | AllplanAttributes - Material: Fensterelement; Tragendes Bauteil: no; Brandabschnittsdefinierendes Bauteil: no; Positionsnummer_Text: U23
Fensteröffnung | H2 Ebene 0 | 1105Fen0000043621 | m³ | 0 | Wärmedämm-Verbundsysteme | Fensteröffnung | 0 | 0 | NEW | 1105Wa 0000001197 | 0 | RC 1 | 0,51 | AllplanAttributes - Material: Fensterelement; Außenliegend: yes; Positionsnummer_Text: U23
Fensteröffnung | H2 Ebene 0 | 1105Fen0000043622 | m³ | 0 | Wärmedämm-Verbundsysteme | Fensteröffnung | 0 | 0 | NEW | 1105Wa 0000001201 | 0 | RC 1 | 0,51 | AllplanAttributes - ash D_Detailverweis: FS 1; ash D_Plannummer: D780; Positionsnummer_Text: U23
Fensteröffnung | H2 Ebene 0 | 1105Fen0000043623 | m² | 0 | Wärmedämm-Verbundsysteme | Fensteröffnung | 0 | 0 | NEW | 1105Wa 0000001205 | 0 | RC 1 | 0,51 | AllplanAttributes - Positionsnummer_Text: U23
Fensteröffnung | H2 Ebene 0 | 1105Fen0000043624 | m² | 0 | Wärmedämm-Verbundsysteme | Fensteröffnung | 0 | 0 | NEW | 1105Wa 0000001209 | 0 | RC 1 | 0,51 | AllplanAttributes - Positionsnummer_Text: U23
Fensteröffnung | H2 Ebene 0 | 1105Fen0000043625 | m² | 0 | Wärmedämm-Verbundsysteme | Fensteröffnung | 0 | 0 | NEW | 1105Wa 0000001213 | 0 | RC 1 | 0,51 | AllplanAttributes - Positionsnummer_Text: U23
Fensteröffnung | H2 Ebene 0 | 1105Fen0000043626 | m² | 0 | Wärmedämm-Verbundsysteme | Fensteröffnung | 0 | 0 | NEW | 1105Wa 0000001217 | 0 | RC 1 | 0,51 | AllplanAttributes - Positionsnummer_Text: U23
Fensteröffnung | H2 Ebene 0 | 1105Fen0000043662 | m² |  | Wärmedämm-Verbundsysteme | Fensteröffnung |  | 0 | NEW | 1105Wa 0000001093 | 0 | RC 1 | 0,51 | AllplanAttributes - Material: Fensterelement; Tragendes Bauteil: no; Brandabschnittsdefinierendes Bauteil: no; Positionsnummer_Text: U23
Fensteröffnung | H2 Ebene 0 | 1105Fen0000043788 | m² |  | Wärmedämm-Verbundsysteme | Fensteröffnung |  | 0 | NEW | 1105Wa 0000001093 | 0 | RC 1 | 0,51 | AllplanAttributes - Material: Fensterelement; Tragendes Bauteil: no; Brandabschnittsdefinierendes Bauteil: no; Positionsnummer_Text: U23
Fensteröffnung | H2 Ebene 0 | 1105Fen0000043663 | m³ | 0 | Wärmedämm-Verbundsysteme | Fensteröffnung | 0 | 0 | NEW | 1105Wa 0000001097 | 0 | RC 1 | 0,51 | AllplanAttributes - Material: Fensterelement; Außenliegend: yes; Positionsnummer_Text: U23
Fensteröffnung | H2 Ebene 0 | 1105Fen0000043789 | m³ | 0 | Wärmedämm-Verbundsysteme | Fensteröffnung | 0 | 0 | NEW | 1105Wa 0000001097 | 0 | RC 1 | 0,51 | AllplanAttributes - Material: Fensterelement; Außenliegend: yes; Positionsnummer_Text: U23
Fensteröffnung | H2 Ebene 0 | 1105Fen0000043664 | m³ | 0 | Wärmedämm-Verbundsysteme | Fensteröffnung | 0 | 0 | NEW | 1105Wa 0000001117 | 0 | RC 1 | 0,51 | AllplanAttributes - Positionsnummer_Text: U23
Fensteröffnung | H2 Ebene 0 | 1105Fen0000043790 | m³ | 0 | Wärmedämm-Verbundsysteme | Fensteröffnung | 0 | 0 | NEW | 1105Wa 0000001117 | 0 | RC 1 | 0,51 | AllplanAttributes - Positionsnummer_Text: U23
Fensteröffnung | H2 Ebene 0 | 1105Fen0000043665 | m² | 0 | Wärmedämm-Verbundsysteme | Fensteröffnung | 0 | 0 | NEW | 1105Wa 0000001113 | 0 | RC 1 | 0,51 | AllplanAttributes - Positionsnummer_Text: U23
Fensteröffnung | H2 Ebene 0 | 1105Fen0000043791 | m² | 0 | Wärmedämm-Verbundsysteme | Fensteröffnung | 0 | 0 | NEW | 1105Wa 0000001113 | 0 | RC 1 | 0,51 | AllplanAttributes - Positionsnummer_Text: U23
Fensteröffnung | H2 Ebene 0 | 1105Fen0000043666 | m² | 0 | Wärmedämm-Verbundsysteme | Fensteröffnung | 0 | 0 | NEW | 1105Wa 0000001109 | 0 | RC 1 | 0,51 | AllplanAttributes - Positionsnummer_Text: U23
Fensteröffnung | H2 Ebene 0 | 1105Fen0000043792 | m² | 0 | Wärmedämm-Verbundsysteme | Fensteröffnung | 0 | 0 | NEW | 1105Wa 0000001109 | 0 | RC 1 | 0,51 | AllplanAttributes - Positionsnummer_Text: U23
Fensteröffnung | H2 Ebene 0 | 1105Fen0000043793 | m² | 0 | Wärmedämm-Verbundsysteme | Fensteröffnung | 0 | 0 | NEW | 1105Wa 0000001105 | 0 | RC 1 | 0,51 | AllplanAttributes - Positionsnummer_Text: U23
Fensteröffnung | H2 Ebene 0 | 1105Fen0000043667 | m² | 0 | Wärmedämm-Verbundsysteme | Fensteröffnung | 0 | 0 | NEW | 1105Wa 0000001105 | 0 | RC 1 | 0,51 | AllplanAttributes - Positionsnummer_Text: U23
Fensteröffnung | H2 Ebene 0 | 1105Fen0000043794 | m² | 0 | Wärmedämm-Verbundsysteme | Fensteröffnung | 0 | 0 | NEW | 1105Wa 0000001101 | 0 | RC 1 | 0,51 | AllplanAttributes - Positionsnummer_Text: U23
Fensteröffnung | H2 Ebene 0 | 1105Fen0000043668 | m² | 0 | Wärmedämm-Verbundsysteme | Fensteröffnung | 0 | 0 | NEW | 1105Wa 0000001101 | 0 | RC 1 | 0,51 | AllplanAttributes - Positionsnummer_Text: U23
Fensteröffnung | H2 Ebene 0 | 1105Fen0000043872 | m² |  | Wärmedämm-Verbundsysteme | Fensteröffnung |  | 0 | NEW | 1105Wa 0000003112 | 0 | RC 1 | 0,51 | AllplanAttributes - Material: Fensterelement; Tragendes Bauteil: no; Brandabschnittsdefinierendes Bauteil: no; Positionsnummer_Text: U23
Fensteröffnung | H2 Ebene 0 | 1105Fen0000043746 | m² |  | Wärmedämm-Verbundsysteme | Fensteröffnung |  | 0 | NEW | 1105Wa 0000003112 | 0 | RC 1 | 0,51 | AllplanAttributes - Material: Fensterelement; Tragendes Bauteil: no; Brandabschnittsdefinierendes Bauteil: no; Positionsnummer_Text: U23
Fensteröffnung | H2 Ebene 0 | 1105Fen0000043873 | m³ | 0 | Wärmedämm-Verbundsysteme | Fensteröffnung | 0 | 0 | NEW | 1105Wa 0000003108 | 0 | RC 1 | 0,51 | AllplanAttributes - Material: Fensterelement; Außenliegend: yes; Positionsnummer_Text: U23
Fensteröffnung | H2 Ebene 0 | 1105Fen0000043747 | m³ | 0 | Wärmedämm-Verbundsysteme | Fensteröffnung | 0 | 0 | NEW | 1105Wa 0000003108 | 0 | RC 1 | 0,51 | AllplanAttributes - Material: Fensterelement; Außenliegend: yes; Positionsnummer_Text: U23
Fensteröffnung | H2 Ebene 0 | 1105Fen0000043748 | m³ | 0 | Wärmedämm-Verbundsysteme | Fensteröffnung | 0 | 0 | NEW | 1105Wa 0000003104 | 0 | RC 1 | 0,51 | AllplanAttributes - Positionsnummer_Text: U23
Fensteröffnung | H2 Ebene 0 | 1105Fen0000043874 | m³ | 0 | Wärmedämm-Verbundsysteme | Fensteröffnung | 0 | 0 | NEW | 1105Wa 0000003104 | 0 | RC 1 | 0,51 | AllplanAttributes - Positionsnummer_Text: U23
Fensteröffnung | H2 Ebene 0 | 1105Fen0000043749 | m² | 0 | Wärmedämm-Verbundsysteme | Fensteröffnung | 0 | 0 | NEW | 1105Wa 0000003100 | 0 | RC 1 | 0,51 | AllplanAttributes - Positionsnummer_Text: U23
Fensteröffnung | H2 Ebene 0 | 1105Fen0000043875 | m² | 0 | Wärmedämm-Verbundsysteme | Fensteröffnung | 0 | 0 | NEW | 1105Wa 0000003100 | 0 | RC 1 | 0,51 | AllplanAttributes - Positionsnummer_Text: U23
Fensteröffnung | H2 Ebene 0 | 1105Fen0000043750 | m² | 0 | Wärmedämm-Verbundsysteme | Fensteröffnung | 0 | 0 | NEW | 1105Wa 0000003096 | 0 | RC 1 | 0,51 | AllplanAttributes - Positionsnummer_Text: U23
Fensteröffnung | H2 Ebene 0 | 1105Fen0000043876 | m² | 0 | Wärmedämm-Verbundsysteme | Fensteröffnung | 0 | 0 | NEW | 1105Wa 0000003096 | 0 | RC 1 | 0,51 | AllplanAttributes - Positionsnummer_Text: U23
Fensteröffnung | H2 Ebene 0 | 1105Fen0000043877 | m² | 0 | Wärmedämm-Verbundsysteme | Fensteröffnung | 0 | 0 | NEW | 1105Wa 0000003092 | 0 | RC 1 | 0,51 | AllplanAttributes - Positionsnummer_Text: U23
Fensteröffnung | H2 Ebene 0 | 1105Fen0000043751 | m² | 0 | Wärmedämm-Verbundsysteme | Fensteröffnung | 0 | 0 | NEW | 1105Wa 0000003092 | 0 | RC 1 | 0,51 | AllplanAttributes - Positionsnummer_Text: U23
Fensteröffnung | H2 Ebene 0 | 1105Fen0000043878 | m² | 0 | Wärmedämm-Verbundsysteme | Fensteröffnung | 0 | 0 | NEW | 1105Wa 0000003088 | 0 | RC 1 | 0,51 | AllplanAttributes - Positionsnummer_Text: U23
Fensteröffnung | H2 Ebene 0 | 1105Fen0000043752 | m² | 0 | Wärmedämm-Verbundsysteme | Fensteröffnung | 0 | 0 | NEW | 1105Wa 0000003088 | 0 | RC 1 | 0,51 | AllplanAttributes - Positionsnummer_Text: U23
Fensteröffnung | H2 Ebene 0 | 1105Fen0000046595 | m² |  | Wärmedämm-Verbundsysteme | Fensteröffnung |  | 0 | NEW | 1105Wa 0000002807 | 0 | RC 1 | 0,51 | AllplanAttributes - Material: Fensterelement; Tragendes Bauteil: no; Brandabschnittsdefinierendes Bauteil: no; U-Wert: 0.9; Positionsnummer_Text: U23
Fensteröffnung | H2 Ebene 0 | 1105Fen2005793900 | m² |  | Wärmedämm-Verbundsysteme | Fensteröffnung |  | 0 | NEW | 1105Wa 0000002807 | 0 | RC 1 | 0,51 | AllplanAttributes - Material: Fensterelement; Tragendes Bauteil: no; Brandabschnittsdefinierendes Bauteil: no; U-Wert: 0.9; Positionsnummer_Text: U23
Fensteröffnung | H2 Ebene 0 | 1105Fen0000046596 | m³ | 0 | Wärmedämm-Verbundsysteme | Fensteröffnung | 0 | 0 | NEW | 1105Wa 0000002803 | 0 | RC 1 | 0,51 | AllplanAttributes - Material: Fensterelement; Außenliegend: yes; U-Wert: 0.9; Positionsnummer_Text: U23
Fensteröffnung | H2 Ebene 0 | 1105Fen2005793896 | m³ | 0 | Wärmedämm-Verbundsysteme | Fensteröffnung | 0 | 0 | NEW | 1105Wa 0000002803 | 0 | RC 1 | 0,51 | AllplanAttributes - Material: Fensterelement; Außenliegend: yes; U-Wert: 0.9; Positionsnummer_Text: U23
Fensteröffnung | H2 Ebene 0 | 1105Fen0000046597 | m³ | 0 | Wärmedämm-Verbundsysteme | Fensteröffnung | 0 | 0 | NEW | 1105Wa 0000002799 | 0 | RC 1 | 0,51 | AllplanAttributes - U-Wert: 0.9; Positionsnummer_Text: U23
Fensteröffnung | H2 Ebene 0 | 1105Fen2005793890 | m³ | 0 | Wärmedämm-Verbundsysteme | Fensteröffnung | 0 | 0 | NEW | 1105Wa 0000002799 | 0 | RC 1 | 0,51 | AllplanAttributes - U-Wert: 0.9; Positionsnummer_Text: U23
Fensteröffnung | H2 Ebene 0 | 1105Fen0000046598 | m² | 0 | Wärmedämm-Verbundsysteme | Fensteröffnung | 0 | 0 | NEW | 1105Wa 0000002795 | 0 | RC 1 | 0,51 | AllplanAttributes - U-Wert: 0.9; Positionsnummer_Text: U23
Fensteröffnung | H2 Ebene 0 | 1105Fen2005793888 | m² | 0 | Wärmedämm-Verbundsysteme | Fensteröffnung | 0 | 0 | NEW | 1105Wa 0000002795 | 0 | RC 1 | 0,51 | AllplanAttributes - U-Wert: 0.9; Positionsnummer_Text: U23
Fensteröffnung | H2 Ebene 0 | 1105Fen0000046599 | m² | 0 | Wärmedämm-Verbundsysteme | Fensteröffnung | 0 | 0 | NEW | 1105Wa 0000002791 | 0 | RC 1 | 0,51 | AllplanAttributes - U-Wert: 0.9; Positionsnummer_Text: U23
Fensteröffnung | H2 Ebene 0 | 1105Fen2005793894 | m² | 0 | Wärmedämm-Verbundsysteme | Fensteröffnung | 0 | 0 | NEW | 1105Wa 0000002791 | 0 | RC 1 | 0,51 | AllplanAttributes - U-Wert: 0.9; Positionsnummer_Text: U23
Fensteröffnung | H2 Ebene 0 | 1105Fen0000046600 | m² | 0 | Wärmedämm-Verbundsysteme | Fensteröffnung | 0 | 0 | NEW | 1105Wa 0000002787 | 0 | RC 1 | 0,51 | AllplanAttributes - U-Wert: 0.9; Positionsnummer_Text: U23
Fensteröffnung | H2 Ebene 0 | 1105Fen2005793898 | m² | 0 | Wärmedämm-Verbundsysteme | Fensteröffnung | 0 | 0 | NEW | 1105Wa 0000002787 | 0 | RC 1 | 0,51 | AllplanAttributes - U-Wert: 0.9; Positionsnummer_Text: U23
Fensteröffnung | H2 Ebene 0 | 1105Fen0000046601 | m² | 0 | Wärmedämm-Verbundsysteme | Fensteröffnung | 0 | 0 | NEW | 1105Wa 0000002783 | 0 | RC 1 | 0,51 | AllplanAttributes - U-Wert: 0.9; Positionsnummer_Text: U23
Fensteröffnung | H2 Ebene 0 | 1105Fen2005793892 | m² | 0 | Wärmedämm-Verbundsysteme | Fensteröffnung | 0 | 0 | NEW | 1105Wa 0000002783 | 0 | RC 1 | 0,51 | AllplanAttributes - U-Wert: 0.9; Positionsnummer_Text: U23
Fensteröffnung | H2 Ebene 0 | 1105Fen0000046427 | m² |  | Wärmedämm-Verbundsysteme | Fensteröffnung |  | 0 | NEW | 1105Wa 0000002572 | 0 | RC 1 | 0,51 | AllplanAttributes - Material: Fensterelement; Tragendes Bauteil: no; Brandabschnittsdefinierendes Bauteil: no; U-Wert: 0.9; Positionsnummer_Text: U23
Fensteröffnung | H2 Ebene 0 | 1105Fen0000046428 | m³ | 0 | Wärmedämm-Verbundsysteme | Fensteröffnung | 0 | 0 | NEW | 1105Wa 0000002576 | 0 | RC 1 | 0,51 | AllplanAttributes - Material: Fensterelement; Außenliegend: yes; U-Wert: 0.9; Positionsnummer_Text: U23
Fensteröffnung | H2 Ebene 0 | 1105Fen0000046429 | m³ | 0 | Wärmedämm-Verbundsysteme | Fensteröffnung | 0 | 0 | NEW | 1105Wa 0000002580 | 0 | RC 1 | 0,51 | AllplanAttributes - U-Wert: 0.9; Positionsnummer_Text: U23
Fensteröffnung | H2 Ebene 0 | 1105Fen0000046430 | m² | 0 | Wärmedämm-Verbundsysteme | Fensteröffnung | 0 | 0 | NEW | 1105Wa 0000002584 | 0 | RC 1 | 0,51 | AllplanAttributes - U-Wert: 0.9; Positionsnummer_Text: U23
Fensteröffnung | H2 Ebene 0 | 1105Fen0000046431 | m² | 0 | Wärmedämm-Verbundsysteme | Fensteröffnung | 0 | 0 | NEW | 1105Wa 0000002588 | 0 | RC 1 | 0,51 | AllplanAttributes - U-Wert: 0.9; Positionsnummer_Text: U23
Fensteröffnung | H2 Ebene 0 | 1105Fen0000046432 | m² | 0 | Wärmedämm-Verbundsysteme | Fensteröffnung | 0 | 0 | NEW | 1105Wa 0000002592 | 0 | RC 1 | 0,51 | AllplanAttributes - U-Wert: 0.9; Positionsnummer_Text: U23
Fensteröffnung | H2 Ebene 0 | 1105Fen0000046433 | m² | 0 | Wärmedämm-Verbundsysteme | Fensteröffnung | 0 | 0 | NEW | 1105Wa 0000002596 | 0 | RC 1 | 0,51 | AllplanAttributes - U-Wert: 0.9; Positionsnummer_Text: U23
Türöffnung | H2 Ebene 0 | 1105Tür0811622513 | m² |  | Trockenbauarbeiten | Türöffnung |  | 0 | NEW | 1105Wa 0000034413 | 0 | RC 1 | 0,51 | AllplanAttributes - Codetext: Codetext; Türanschlag: DIN R; Positionsnummer_Text: U23; Pset_OpeningElementCommon - FireExit: no; Reference: Codetext
Türöffnung | H2 Ebene 0 | 1105Tür0811622515 | m³ | 0 | Trockenbauarbeiten | Türöffnung | 0 | 0 | NEW | 1105Wa 0000034414 | 0 | RC 1 | 0,51 | AllplanAttributes - Türanschlag: DIN R; Positionsnummer_Text: U23
Türöffnung | H2 Ebene 0 | 1105Tür0811622517 | m³ | 0 | Trockenbauarbeiten | Türöffnung | 0 | 0 | NEW | 1105Wa 0000034415 | 0 | RC 1 | 0,51 | AllplanAttributes - Türanschlag: DIN R; Positionsnummer_Text: U23
Türöffnung | H2 Ebene 0 | 1105Tür0811622519 | m² | 0 | Trockenbauarbeiten | Türöffnung | 0 | 0 | NEW | 1105Wa 0000034416 | 0 | RC 1 | 0,51 | AllplanAttributes - Türanschlag: DIN R; Positionsnummer_Text: U23
Türöffnung | H2 Ebene 0 | 1105Tür0811622521 | m² | 0 | Trockenbauarbeiten | Türöffnung | 0 | 0 | NEW | 1105Wa 0000034417 | 0 | RC 1 | 0,51 | AllplanAttributes - Türanschlag: DIN R; Positionsnummer_Text: U23
Türöffnung | H2 Ebene 0 | 1105Tür0811622523 | m² | 0 | Trockenbauarbeiten | Türöffnung | 0 | 0 | NEW | 1105Wa 0000034418 | 0 | RC 1 | 0,51 | AllplanAttributes - Türanschlag: DIN R; Positionsnummer_Text: U23
Türöffnung | H2 Ebene 0 | 1105Tür0811622525 | m² | 0 | Trockenbauarbeiten | Türöffnung | 0 | 0 | NEW | 1105Wa 0000034419 | 0 | RC 1 | 0,51 | AllplanAttributes - Türanschlag: DIN R; Positionsnummer_Text: U23
Fensteröffnung | H2 Ebene 0 | 1105Fen0811567026 | m² |  | Fensterarbeiten | Fensteröffnung |  | 0 |  | 1105Wa 0811567043 | 0 | RC 1 | 0,51 | AllplanAttributes - U-Wert: 0.9; Positionsnummer_Text: U23
Fensteröffnung | H2 Ebene 0 | 1105Fen0811567022 | m² |  | Fensterarbeiten | Fensteröffnung |  | 0 |  | 1105Wa 0811567043 | 0 | RC 1 | 0,51 | AllplanAttributes - U-Wert: 0.9; Positionsnummer_Text: U23
Fensteröffnung | H2 Ebene 0 | 1105Fen0811567024 | m² |  | Fensterarbeiten | Fensteröffnung |  | 0 |  | 1105Wa 0811567043 | 0 | RC 1 | 0,51 | AllplanAttributes - U-Wert: 0.9; Positionsnummer_Text: U23
Fensteröffnung | H2 Ebene 0 | 1105Fen0811567025 | m² |  | Fensterarbeiten | Fensteröffnung |  | 0 |  | 1105Wa 0811567043 | 0 | RC 1 | 0,51 | AllplanAttributes - U-Wert: 0.9; Positionsnummer_Text: U23
Fensteröffnung | H2 Ebene 0 | 1105Fen0811567027 | m³ | 0 | Fensterarbeiten | Fensteröffnung | 0 | 0 |  | 1105Wa 0811567042 | 0 | RC 1 | 0,51 | AllplanAttributes - U-Wert: 0.9; Positionsnummer_Text: U23
Fensteröffnung | H2 Ebene 0 | 1105Fen0811567021 | m³ | 0 | Fensterarbeiten | Fensteröffnung | 0 | 0 |  | 1105Wa 0811567042 | 0 | RC 1 | 0,51 | AllplanAttributes - U-Wert: 0.9; Positionsnummer_Text: U23
Fensteröffnung | H2 Ebene 0 | 1105Fen0811567028 | m³ | 0 | Fensterarbeiten | Fensteröffnung | 0 | 0 |  | 1105Wa 0811567042 | 0 | RC 1 | 0,51 | AllplanAttributes - U-Wert: 0.9; Positionsnummer_Text: U23
Fensteröffnung | H2 Ebene 0 | 1105Fen0811567023 | m³ | 0 | Fensterarbeiten | Fensteröffnung | 0 | 0 |  | 1105Wa 0811567042 | 0 | RC 1 | 0,51 | AllplanAttributes - U-Wert: 0.9; Positionsnummer_Text: U23
Fensteröffnung | H2 Ebene 0 | 1105Fen0811567029 | m³ | 0 | Fensterarbeiten | Fensteröffnung | 0 | 0 |  | 1105Wa 0811567041 | 0 | RC 1 | 0,51 | AllplanAttributes - U-Wert: 0.9; Positionsnummer_Text: U23
Fensteröffnung | H2 Ebene 0 | 1105Fen0811567031 | m³ | 0 | Fensterarbeiten | Fensteröffnung | 0 | 0 |  | 1105Wa 0811567041 | 0 | RC 1 | 0,51 | AllplanAttributes - U-Wert: 0.9; Positionsnummer_Text: U23
Fensteröffnung | H2 Ebene 0 | 1105Fen0811567032 | m³ | 0 | Fensterarbeiten | Fensteröffnung | 0 | 0 |  | 1105Wa 0811567041 | 0 | RC 1 | 0,51 | AllplanAttributes - U-Wert: 0.9; Positionsnummer_Text: U23
Fensteröffnung | H2 Ebene 0 | 1105Fen0811567030 | m³ | 0 | Fensterarbeiten | Fensteröffnung | 0 | 0 |  | 1105Wa 0811567041 | 0 | RC 1 | 0,51 | AllplanAttributes - U-Wert: 0.9; Positionsnummer_Text: U23
Fensteröffnung | H2 Ebene 0 | 1105Fen0811567033 | m² | 0 | Fensterarbeiten | Fensteröffnung | 0 | 0 |  | 1105Wa 0811567040 | 0 | RC 1 | 0,51 | AllplanAttributes - U-Wert: 0.9; Positionsnummer_Text: U23
Fensteröffnung | H2 Ebene 0 | 1105Fen0811567035 | m² | 0 | Fensterarbeiten | Fensteröffnung | 0 | 0 |  | 1105Wa 0811567040 | 0 | RC 1 | 0,51 | AllplanAttributes - U-Wert: 0.9; Positionsnummer_Text: U23
Fensteröffnung | H2 Ebene 0 | 1105Fen0811567034 | m² | 0 | Fensterarbeiten | Fensteröffnung | 0 | 0 |  | 1105Wa 0811567040 | 0 | RC 1 | 0,51 | AllplanAttributes - U-Wert: 0.9; Positionsnummer_Text: U23
Fensteröffnung | H2 Ebene 0 | 1105Fen0811567036 | m² | 0 | Fensterarbeiten | Fensteröffnung | 0 | 0 |  | 1105Wa 0811567040 | 0 | RC 1 | 0,51 | AllplanAttributes - U-Wert: 0.9; Positionsnummer_Text: U23
Fensteröffnung | H2 Ebene 0 | 1105Fen0811567011 | m² | 0 | Fensterarbeiten | Fensteröffnung | 0 | 0 | NEW | 1105Wa 0811567039 | 0 | RC 1 | 0,51 | AllplanAttributes - U-Wert: 0.9; Positionsnummer_Text: U23
Fensteröffnung | H2 Ebene 0 | 1105Fen0811567017 | m² | 0 | Fensterarbeiten | Fensteröffnung | 0 | 0 | NEW | 1105Wa 0811567039 | 0 | RC 1 | 0,51 | AllplanAttributes - U-Wert: 0.9; Positionsnummer_Text: U23
Fensteröffnung | H2 Ebene 0 | 1105Fen0811567020 | m² | 0 | Fensterarbeiten | Fensteröffnung | 0 | 0 | NEW | 1105Wa 0811567039 | 0 | RC 1 | 0,51 | AllplanAttributes - U-Wert: 0.9; Positionsnummer_Text: U23
Fensteröffnung | H2 Ebene 0 | 1105Fen0811567014 | m² | 0 | Fensterarbeiten | Fensteröffnung | 0 | 0 | NEW | 1105Wa 0811567039 | 0 | RC 1 | 0,51 | AllplanAttributes - U-Wert: 0.9; Positionsnummer_Text: U23
Fensteröffnung | H2 Ebene 0 | 1105Fen0811567013 | m² | 0 | Fensterarbeiten | Fensteröffnung | 0 | 0 | NEW | 1105Wa 0811567038 | 0 | RC 1 | 0,51 | AllplanAttributes - U-Wert: 0.9; Positionsnummer_Text: U23
Fensteröffnung | H2 Ebene 0 | 1105Fen0811567019 | m² | 0 | Fensterarbeiten | Fensteröffnung | 0 | 0 | NEW | 1105Wa 0811567038 | 0 | RC 1 | 0,51 | AllplanAttributes - U-Wert: 0.9; Positionsnummer_Text: U23
Fensteröffnung | H2 Ebene 0 | 1105Fen0811567016 | m² | 0 | Fensterarbeiten | Fensteröffnung | 0 | 0 | NEW | 1105Wa 0811567038 | 0 | RC 1 | 0,51 | AllplanAttributes - U-Wert: 0.9; Positionsnummer_Text: U23
Fensteröffnung | H2 Ebene 0 | 1105Fen0811567010 | m² | 0 | Fensterarbeiten | Fensteröffnung | 0 | 0 | NEW | 1105Wa 0811567038 | 0 | RC 1 | 0,51 | AllplanAttributes - U-Wert: 0.9; Positionsnummer_Text: U23
Fensteröffnung | H2 Ebene 0 | 1105Fen0811567018 | m² | 0 | Fensterarbeiten | Fensteröffnung | 0 | 0 | NEW | 1105Wa 0811567037 | 0 | RC 1 | 0,51 | AllplanAttributes - U-Wert: 0.9; Positionsnummer_Text: U23
Fensteröffnung | H2 Ebene 0 | 1105Fen0811567012 | m² | 0 | Fensterarbeiten | Fensteröffnung | 0 | 0 | NEW | 1105Wa 0811567037 | 0 | RC 1 | 0,51 | AllplanAttributes - U-Wert: 0.9; Positionsnummer_Text: U23
Fensteröffnung | H2 Ebene 0 | 1105Fen0811567015 | m² | 0 | Fensterarbeiten | Fensteröffnung | 0 | 0 | NEW | 1105Wa 0811567037 | 0 | RC 1 | 0,51 | AllplanAttributes - U-Wert: 0.9; Positionsnummer_Text: U23
Fensteröffnung | H2 Ebene 0 | 1105Fen0811567009 | m² | 0 | Fensterarbeiten | Fensteröffnung | 0 | 0 | NEW | 1105Wa 0811567037 | 0 | RC 1 | 0,51 | AllplanAttributes - U-Wert: 0.9; Positionsnummer_Text: U23
Türöffnung | H2 Ebene 0 | 1105Tür0811567306 | m² |  | Trockenbauarbeiten | Türöffnung |  | 0 | NEW | 1105Wa 0811567313 | 0 | RC 1 | 0,51 | AllplanAttributes - Codetext: Codetext; Türanschlag: DIN L; Positionsnummer_Text: U23; Pset_OpeningElementCommon - FireExit: no; Reference: Codetext
Türöffnung | H2 Ebene 0 | 1105Tür0811567307 | m³ | 0 | Trockenbauarbeiten | Türöffnung | 0 | 0 | NEW | 1105Wa 0811567314 | 0 | RC 1 | 0,51 | AllplanAttributes - Türanschlag: DIN L; Positionsnummer_Text: U23
Türöffnung | H2 Ebene 0 | 1105Tür0811567308 | m³ | 0 | Trockenbauarbeiten | Türöffnung | 0 | 0 | NEW | 1105Wa 0811567315 | 0 | RC 1 | 0,51 | AllplanAttributes - Türanschlag: DIN L; Positionsnummer_Text: U23
Türöffnung | H2 Ebene 0 | 1105Tür0811567309 | m² | 0 | Trockenbauarbeiten | Türöffnung | 0 | 0 | NEW | 1105Wa 0811567316 | 0 | RC 1 | 0,51 | AllplanAttributes - Türanschlag: DIN L; Positionsnummer_Text: U23
Türöffnung | H2 Ebene 0 | 1105Tür0811567310 | m² | 0 | Trockenbauarbeiten | Türöffnung | 0 | 0 | NEW | 1105Wa 0811567317 | 0 | RC 1 | 0,51 | AllplanAttributes - Türanschlag: DIN L; Positionsnummer_Text: U23
Türöffnung | H2 Ebene 0 | 1105Tür0811567311 | m² | 0 | Trockenbauarbeiten | Türöffnung | 0 | 0 | NEW | 1105Wa 0811567318 | 0 | RC 1 | 0,51 | AllplanAttributes - Türanschlag: DIN L; Positionsnummer_Text: U23
Türöffnung | H2 Ebene 0 | 1105Tür0811567312 | m² | 0 | Trockenbauarbeiten | Türöffnung | 0 | 0 | NEW | 1105Wa 0811567319 | 0 | RC 1 | 0,51 | AllplanAttributes - Türanschlag: DIN L; Positionsnummer_Text: U23
Fensteröffnung | H2 Ebene 0 | 1105Fen0000040100 | m² |  | Wärmedämm-Verbundsysteme | Fensteröffnung |  | 7.5 | NEW | 1105Wa 0000002063 | 0 | RC 1 | 0,51 | AllplanAttributes - Material: Fensterelement; Tragendes Bauteil: no; Brandabschnittsdefinierendes Bauteil: no; Positionsnummer_Text: U23
Fensteröffnung | H2 Ebene 0 | 1105Fen0000040101 | m³ | 0 | Wärmedämm-Verbundsysteme | Fensteröffnung | 0 | 7.5 | NEW | 1105Wa 0000002059 | 0 | RC 1 | 0,51 | AllplanAttributes - Material: Fensterelement; Außenliegend: yes; Positionsnummer_Text: U23
Fensteröffnung | H2 Ebene 0 | 1105Fen0000040102 | m³ | 0 | Wärmedämm-Verbundsysteme | Fensteröffnung | 0 | 7.5 | NEW | 1105Wa 0000002055 | 0 | RC 1 | 0,51 | AllplanAttributes - Positionsnummer_Text: U23
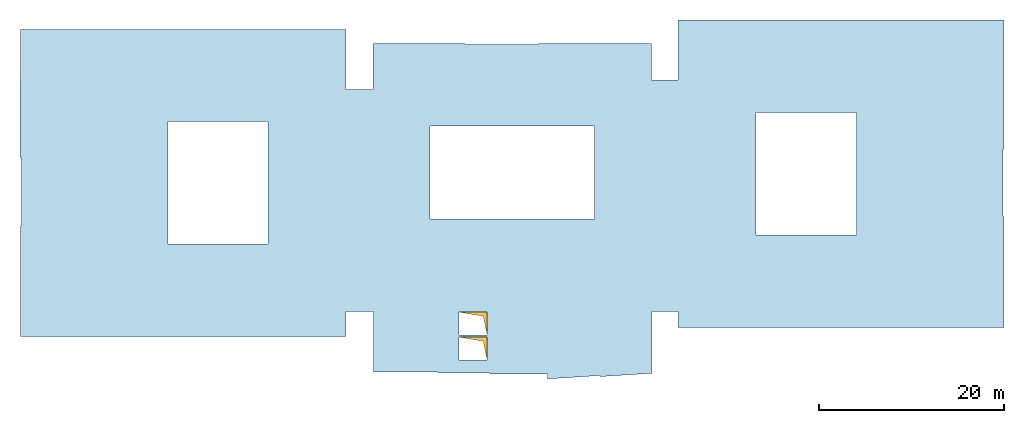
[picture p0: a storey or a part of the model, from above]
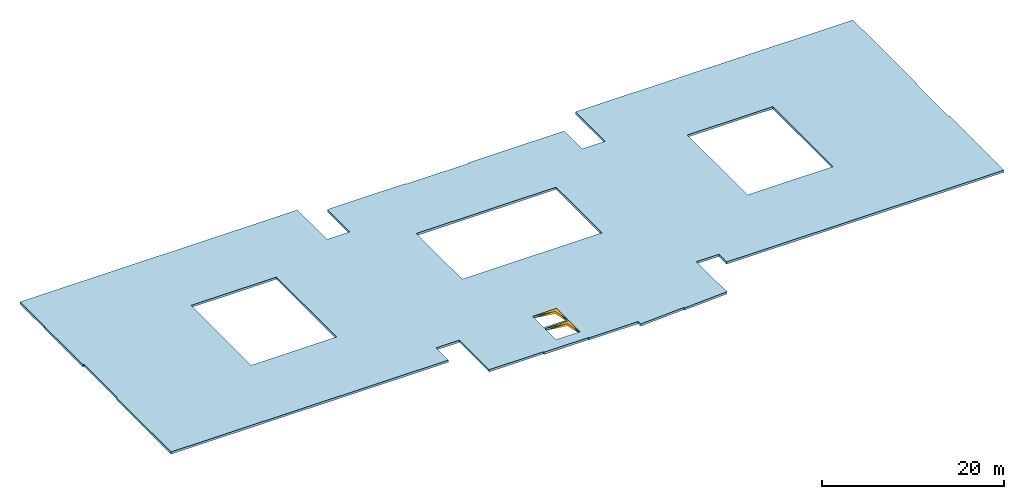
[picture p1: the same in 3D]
Properties of the parts of a building model (IFC4), part 41 of 80

# IfcOpeningElement: Opening (3497)
Name | In | Allright_Bauteil_ID | Abrechnungsart | Versatz_oben | Gewerk | Objektname | Versatz_unten | OKFF | Status | P_ID | AllplanAttributes, Feuerwiderstandsklasse | Sicherheitsklasse | g-Wert
Fensteröffnung | H2 Ebene 0 | 1105Fen0000040103 | m² | 0 | Wärmedämm-Verbundsysteme | Fensteröffnung | 0 | 7.5 | NEW | 1105Wa 0000002051 | 0 | RC 1 | 0,51 | AllplanAttributes - Positionsnummer_Text: U23
Fensteröffnung | H2 Ebene 0 | 1105Fen0000040104 | m² | 0 | Wärmedämm-Verbundsysteme | Fensteröffnung | 0 | 7.5 | NEW | 1105Wa 0000002047 | 0 | RC 1 | 0,51 | AllplanAttributes - Positionsnummer_Text: U23
Fensteröffnung | H2 Ebene 0 | 1105Fen0000040105 | m² | 0 | Wärmedämm-Verbundsysteme | Fensteröffnung | 0 | 7.5 | NEW | 1105Wa 0000002043 | 0 | RC 1 | 0,51 | AllplanAttributes - Positionsnummer_Text: U23
Fensteröffnung | H2 Ebene 0 | 1105Fen0000040106 | m² | 0 | Wärmedämm-Verbundsysteme | Fensteröffnung | 0 | 7.5 | NEW | 1105Wa 0000002039 | 0 | RC 1 | 0,51 | AllplanAttributes - Positionsnummer_Text: U23
Fensteröffnung | H2 Ebene 0 | 1105Fen0000050002 | m² | 0 | Fensterarbeiten | Fensteröffnung | 0 | 0 |  | 1105Wa 0000003947 | 0 | RC 1 | 0,51 | AllplanAttributes - Positionsnummer_Text: U23
Fensteröffnung | H2 Ebene 0 | 1105Fen0000049960 | m² | 0 | Fensterarbeiten | Fensteröffnung | 0 | 0 |  | 1105Wa 0000003947 | 0 | RC 1 | 0,51 | AllplanAttributes - Positionsnummer_Text: U23
Fensteröffnung | H2 Ebene 0 | 1105Fen2005775883 | m² | 0 | Fensterarbeiten | Fensteröffnung | 0 | 0 |  | 1105Wa 0000003947 | 0 | RC 1 | 0,51 | AllplanAttributes - Positionsnummer_Text: U23
Fensteröffnung | H2 Ebene 0 | 1105Fen0000049876 | m² | 0 | Fensterarbeiten | Fensteröffnung | 0 | 0 |  | 1105Wa 0000003947 | 0 | RC 1 | 0,51 | AllplanAttributes - Positionsnummer_Text: U23
Fensteröffnung | H2 Ebene 0 | 1105Fen0000049918 | m² | 0 | Fensterarbeiten | Fensteröffnung | 0 | 0 |  | 1105Wa 0000003947 | 0 | RC 1 | 0,51 | AllplanAttributes - Positionsnummer_Text: U23
Fensteröffnung | H2 Ebene 0 | 1105Fen0000050001 | m³ | 0 | Fensterarbeiten | Fensteröffnung | 0 | 0 |  | 1105Wa 0000003957 | 0 | RC 1 | 0,51 | AllplanAttributes - Positionsnummer_Text: U23
Fensteröffnung | H2 Ebene 0 | 1105Fen0000049959 | m³ | 0 | Fensterarbeiten | Fensteröffnung | 0 | 0 |  | 1105Wa 0000003957 | 0 | RC 1 | 0,51 | AllplanAttributes - Positionsnummer_Text: U23
Fensteröffnung | H2 Ebene 0 | 1105Fen2005775882 | m³ | 0 | Fensterarbeiten | Fensteröffnung | 0 | 0 |  | 1105Wa 0000003957 | 0 | RC 1 | 0,51 | AllplanAttributes - Positionsnummer_Text: U23
Fensteröffnung | H2 Ebene 0 | 1105Fen0000049875 | m³ | 0 | Fensterarbeiten | Fensteröffnung | 0 | 0 |  | 1105Wa 0000003957 | 0 | RC 1 | 0,51 | AllplanAttributes - Positionsnummer_Text: U23
Fensteröffnung | H2 Ebene 0 | 1105Fen0000049917 | m³ | 0 | Fensterarbeiten | Fensteröffnung | 0 | 0 |  | 1105Wa 0000003957 | 0 | RC 1 | 0,51 | AllplanAttributes - Positionsnummer_Text: U23
Fensteröffnung | H2 Ebene 0 | 1105Fen0000050000 | m³ | 0 | Fensterarbeiten | Fensteröffnung | 0 | 0 |  | 1105Wa 0000003966 | 0 | RC 1 | 0,51 | AllplanAttributes - Positionsnummer_Text: U23
Fensteröffnung | H2 Ebene 0 | 1105Fen0000049958 | m³ | 0 | Fensterarbeiten | Fensteröffnung | 0 | 0 |  | 1105Wa 0000003966 | 0 | RC 1 | 0,51 | AllplanAttributes - Positionsnummer_Text: U23
Fensteröffnung | H2 Ebene 0 | 1105Fen2005775881 | m³ | 0 | Fensterarbeiten | Fensteröffnung | 0 | 0 |  | 1105Wa 0000003966 | 0 | RC 1 | 0,51 | AllplanAttributes - Positionsnummer_Text: U23
Fensteröffnung | H2 Ebene 0 | 1105Fen0000049874 | m³ | 0 | Fensterarbeiten | Fensteröffnung | 0 | 0 |  | 1105Wa 0000003966 | 0 | RC 1 | 0,51 | AllplanAttributes - Positionsnummer_Text: U23
Fensteröffnung | H2 Ebene 0 | 1105Fen0000049916 | m³ | 0 | Fensterarbeiten | Fensteröffnung | 0 | 0 |  | 1105Wa 0000003966 | 0 | RC 1 | 0,51 | AllplanAttributes - Positionsnummer_Text: U23
Fensteröffnung | H2 Ebene 0 | 1105Fen0000049999 | m² | 0 | Fensterarbeiten | Fensteröffnung | 0 | 0 |  | 1105Wa 0000003976 | 0 | RC 1 | 0,51 | AllplanAttributes - Positionsnummer_Text: U23
Fensteröffnung | H2 Ebene 0 | 1105Fen0000049957 | m² | 0 | Fensterarbeiten | Fensteröffnung | 0 | 0 |  | 1105Wa 0000003976 | 0 | RC 1 | 0,51 | AllplanAttributes - Positionsnummer_Text: U23
Fensteröffnung | H2 Ebene 0 | 1105Fen2005775880 | m² | 0 | Fensterarbeiten | Fensteröffnung | 0 | 0 |  | 1105Wa 0000003976 | 0 | RC 1 | 0,51 | AllplanAttributes - Positionsnummer_Text: U23
Fensteröffnung | H2 Ebene 0 | 1105Fen0000049873 | m² | 0 | Fensterarbeiten | Fensteröffnung | 0 | 0 |  | 1105Wa 0000003976 | 0 | RC 1 | 0,51 | AllplanAttributes - Positionsnummer_Text: U23
Fensteröffnung | H2 Ebene 0 | 1105Fen0000049915 | m² | 0 | Fensterarbeiten | Fensteröffnung | 0 | 0 |  | 1105Wa 0000003976 | 0 | RC 1 | 0,51 | AllplanAttributes - Positionsnummer_Text: U23
Fensteröffnung | H2 Ebene 0 | 1105Fen0000049956 | m² | 0 | Fensterarbeiten | Fensteröffnung | 0 | 0 | NEW | 1105Wa 0000003986 | 0 | RC 1 | 0,51 | AllplanAttributes - Positionsnummer_Text: U23
Fensteröffnung | H2 Ebene 0 | 1105Fen0000049998 | m² | 0 | Fensterarbeiten | Fensteröffnung | 0 | 0 | NEW | 1105Wa 0000003986 | 0 | RC 1 | 0,51 | AllplanAttributes - Positionsnummer_Text: U23
Fensteröffnung | H2 Ebene 0 | 1105Fen2005775879 | m² | 0 | Fensterarbeiten | Fensteröffnung | 0 | 0 | NEW | 1105Wa 0000003986 | 0 | RC 1 | 0,51 | AllplanAttributes - Positionsnummer_Text: U23
Fensteröffnung | H2 Ebene 0 | 1105Fen0000049872 | m² | 0 | Fensterarbeiten | Fensteröffnung | 0 | 0 | NEW | 1105Wa 0000003986 | 0 | RC 1 | 0,51 | AllplanAttributes - Positionsnummer_Text: U23
Fensteröffnung | H2 Ebene 0 | 1105Fen0000049914 | m² | 0 | Fensterarbeiten | Fensteröffnung | 0 | 0 | NEW | 1105Wa 0000003986 | 0 | RC 1 | 0,51 | AllplanAttributes - Positionsnummer_Text: U23
Fensteröffnung | H2 Ebene 0 | 1105Fen0000049955 | m² | 0 | Fensterarbeiten | Fensteröffnung | 0 | 0 | NEW | 1105Wa 0000003996 | 0 | RC 1 | 0,51 | AllplanAttributes - Positionsnummer_Text: U23
Fensteröffnung | H2 Ebene 0 | 1105Fen0000049997 | m² | 0 | Fensterarbeiten | Fensteröffnung | 0 | 0 | NEW | 1105Wa 0000003996 | 0 | RC 1 | 0,51 | AllplanAttributes - Positionsnummer_Text: U23
Fensteröffnung | H2 Ebene 0 | 1105Fen2005775878 | m² | 0 | Fensterarbeiten | Fensteröffnung | 0 | 0 | NEW | 1105Wa 0000003996 | 0 | RC 1 | 0,51 | AllplanAttributes - Positionsnummer_Text: U23
Fensteröffnung | H2 Ebene 0 | 1105Fen0000049871 | m² | 0 | Fensterarbeiten | Fensteröffnung | 0 | 0 | NEW | 1105Wa 0000003996 | 0 | RC 1 | 0,51 | AllplanAttributes - Positionsnummer_Text: U23
Fensteröffnung | H2 Ebene 0 | 1105Fen0000049913 | m² | 0 | Fensterarbeiten | Fensteröffnung | 0 | 0 | NEW | 1105Wa 0000003996 | 0 | RC 1 | 0,51 | AllplanAttributes - Positionsnummer_Text: U23
Fensteröffnung | H2 Ebene 0 | 1105Fen0000049954 | m² | 0 | Fensterarbeiten | Fensteröffnung | 0 | 0 | NEW | 1105Wa 0000004006 | 0 | RC 1 | 0,51 | AllplanAttributes - Positionsnummer_Text: U23
Fensteröffnung | H2 Ebene 0 | 1105Fen0000049996 | m² | 0 | Fensterarbeiten | Fensteröffnung | 0 | 0 | NEW | 1105Wa 0000004006 | 0 | RC 1 | 0,51 | AllplanAttributes - Positionsnummer_Text: U23
Fensteröffnung | H2 Ebene 0 | 1105Fen2005775877 | m² | 0 | Fensterarbeiten | Fensteröffnung | 0 | 0 | NEW | 1105Wa 0000004006 | 0 | RC 1 | 0,51 | AllplanAttributes - Positionsnummer_Text: U23
Fensteröffnung | H2 Ebene 0 | 1105Fen0000049870 | m² | 0 | Fensterarbeiten | Fensteröffnung | 0 | 0 | NEW | 1105Wa 0000004006 | 0 | RC 1 | 0,51 | AllplanAttributes - Positionsnummer_Text: U23
Fensteröffnung | H2 Ebene 0 | 1105Fen0000049912 | m² | 0 | Fensterarbeiten | Fensteröffnung | 0 | 0 | NEW | 1105Wa 0000004006 | 0 | RC 1 | 0,51 | AllplanAttributes - Positionsnummer_Text: U23
Fensteröffnung | H2 Ebene 0 | 1105Fen0000047518 | m² |  | Fensterarbeiten | Fensteröffnung |  | 0 |  | 1105Wa 0000002699 | 0 | RC 1 | 0,51 | AllplanAttributes - U-Wert: 0.9; Positionsnummer_Text: U23
Fensteröffnung | H2 Ebene 0 | 1105Fen0000047396 | m² |  | Fensterarbeiten | Fensteröffnung |  | 0 |  | 1105Wa 0000002699 | 0 | RC 1 | 0,51 | AllplanAttributes - U-Wert: 0.9; Positionsnummer_Text: U23
Fensteröffnung | H2 Ebene 0 | 1105Fen0000047354 | m² |  | Fensterarbeiten | Fensteröffnung |  | 0 |  | 1105Wa 0000002699 | 0 | RC 1 | 0,51 | AllplanAttributes - U-Wert: 0.9; Positionsnummer_Text: U23
Fensteröffnung | H2 Ebene 0 | 1105Fen2005771960 | m² | 0 | Fensterarbeiten | Fensteröffnung | 0 | 0 |  | 1105Wa 0000002699 | 0 | RC 1 | 0,51 | AllplanAttributes - U-Wert: 0.9; Positionsnummer_Text: U23
Fensteröffnung | H2 Ebene 0 | 1105Fen0000047517 | m³ | 0 | Fensterarbeiten | Fensteröffnung | 0 | 0 |  | 1105Wa 0000002706 | 0 | RC 1 | 0,51 | AllplanAttributes - U-Wert: 0.9; Positionsnummer_Text: U23
Fensteröffnung | H2 Ebene 0 | 1105Fen0000047353 | m³ | 0 | Fensterarbeiten | Fensteröffnung | 0 | 0 |  | 1105Wa 0000002706 | 0 | RC 1 | 0,51 | AllplanAttributes - U-Wert: 0.9; Positionsnummer_Text: U23
Fensteröffnung | H2 Ebene 0 | 1105Fen0000047395 | m³ | 0 | Fensterarbeiten | Fensteröffnung | 0 | 0 |  | 1105Wa 0000002706 | 0 | RC 1 | 0,51 | AllplanAttributes - U-Wert: 0.9; Positionsnummer_Text: U23
Fensteröffnung | H2 Ebene 0 | 1105Fen2005771959 | m³ | 0 | Fensterarbeiten | Fensteröffnung | 0 | 0 |  | 1105Wa 0000002706 | 0 | RC 1 | 0,51 | AllplanAttributes - U-Wert: 0.9; Positionsnummer_Text: U23
Fensteröffnung | H2 Ebene 0 | 1105Fen0000047516 | m³ | 0 | Fensterarbeiten | Fensteröffnung | 0 | 0 |  | 1105Wa 0000002713 | 0 | RC 1 | 0,51 | AllplanAttributes - U-Wert: 0.9; Positionsnummer_Text: U23
Fensteröffnung | H2 Ebene 0 | 1105Fen0000047352 | m³ | 0 | Fensterarbeiten | Fensteröffnung | 0 | 0 |  | 1105Wa 0000002713 | 0 | RC 1 | 0,51 | AllplanAttributes - U-Wert: 0.9; Positionsnummer_Text: U23
Fensteröffnung | H2 Ebene 0 | 1105Fen0000047394 | m³ | 0 | Fensterarbeiten | Fensteröffnung | 0 | 0 |  | 1105Wa 0000002713 | 0 | RC 1 | 0,51 | AllplanAttributes - U-Wert: 0.9; Positionsnummer_Text: U23
Fensteröffnung | H2 Ebene 0 | 1105Fen2005771958 | m³ | 0 | Fensterarbeiten | Fensteröffnung | 0 | 0 |  | 1105Wa 0000002713 | 0 | RC 1 | 0,51 | AllplanAttributes - U-Wert: 0.9; Positionsnummer_Text: U23
Fensteröffnung | H2 Ebene 0 | 1105Fen0000047515 | m² | 0 | Fensterarbeiten | Fensteröffnung | 0 | 0 |  | 1105Wa 0000002720 | 0 | RC 1 | 0,51 | AllplanAttributes - U-Wert: 0.9; Positionsnummer_Text: U23
Fensteröffnung | H2 Ebene 0 | 1105Fen0000047351 | m² | 0 | Fensterarbeiten | Fensteröffnung | 0 | 0 |  | 1105Wa 0000002720 | 0 | RC 1 | 0,51 | AllplanAttributes - U-Wert: 0.9; Positionsnummer_Text: U23
Fensteröffnung | H2 Ebene 0 | 1105Fen0000047393 | m² | 0 | Fensterarbeiten | Fensteröffnung | 0 | 0 |  | 1105Wa 0000002720 | 0 | RC 1 | 0,51 | AllplanAttributes - U-Wert: 0.9; Positionsnummer_Text: U23
Fensteröffnung | H2 Ebene 0 | 1105Fen2005771957 | m² | 0 | Fensterarbeiten | Fensteröffnung | 0 | 0 |  | 1105Wa 0000002720 | 0 | RC 1 | 0,51 | AllplanAttributes - U-Wert: 0.9; Positionsnummer_Text: U23
Fensteröffnung | H2 Ebene 0 | 1105Fen0000047514 | m² | 0 | Fensterarbeiten | Fensteröffnung | 0 | 0 | NEW | 1105Wa 0000002727 | 0 | RC 1 | 0,51 | AllplanAttributes - U-Wert: 0.9; Positionsnummer_Text: U23
Fensteröffnung | H2 Ebene 0 | 1105Fen0000047350 | m² | 0 | Fensterarbeiten | Fensteröffnung | 0 | 0 | NEW | 1105Wa 0000002727 | 0 | RC 1 | 0,51 | AllplanAttributes - U-Wert: 0.9; Positionsnummer_Text: U23
Fensteröffnung | H2 Ebene 0 | 1105Fen0000047392 | m² | 0 | Fensterarbeiten | Fensteröffnung | 0 | 0 | NEW | 1105Wa 0000002727 | 0 | RC 1 | 0,51 | AllplanAttributes - U-Wert: 0.9; Positionsnummer_Text: U23
Fensteröffnung | H2 Ebene 0 | 1105Fen2005771956 | m² | 0 | Fensterarbeiten | Fensteröffnung | 0 | 0 | NEW | 1105Wa 0000002727 | 0 | RC 1 | 0,51 | AllplanAttributes - U-Wert: 0.9; Positionsnummer_Text: U23
Fensteröffnung | H2 Ebene 0 | 1105Fen0000047513 | m² | 0 | Fensterarbeiten | Fensteröffnung | 0 | 0 | NEW | 1105Wa 0000002734 | 0 | RC 1 | 0,51 | AllplanAttributes - U-Wert: 0.9; Positionsnummer_Text: U23
Fensteröffnung | H2 Ebene 0 | 1105Fen0000047391 | m² | 0 | Fensterarbeiten | Fensteröffnung | 0 | 0 | NEW | 1105Wa 0000002734 | 0 | RC 1 | 0,51 | AllplanAttributes - U-Wert: 0.9; Positionsnummer_Text: U23
Fensteröffnung | H2 Ebene 0 | 1105Fen0000047349 | m² | 0 | Fensterarbeiten | Fensteröffnung | 0 | 0 | NEW | 1105Wa 0000002734 | 0 | RC 1 | 0,51 | AllplanAttributes - U-Wert: 0.9; Positionsnummer_Text: U23
Fensteröffnung | H2 Ebene 0 | 1105Fen2005771955 | m² | 0 | Fensterarbeiten | Fensteröffnung | 0 | 0 | NEW | 1105Wa 0000002734 | 0 | RC 1 | 0,51 | AllplanAttributes - U-Wert: 0.9; Positionsnummer_Text: U23
Fensteröffnung | H2 Ebene 0 | 1105Fen0000047512 | m² | 0 | Fensterarbeiten | Fensteröffnung | 0 | 0 | NEW | 1105Wa 0000002741 | 0 | RC 1 | 0,51 | AllplanAttributes - U-Wert: 0.9; Positionsnummer_Text: U23
Fensteröffnung | H2 Ebene 0 | 1105Fen0000047348 | m² | 0 | Fensterarbeiten | Fensteröffnung | 0 | 0 | NEW | 1105Wa 0000002741 | 0 | RC 1 | 0,51 | AllplanAttributes - U-Wert: 0.9; Positionsnummer_Text: U23
Fensteröffnung | H2 Ebene 0 | 1105Fen0000047390 | m² | 0 | Fensterarbeiten | Fensteröffnung | 0 | 0 | NEW | 1105Wa 0000002741 | 0 | RC 1 | 0,51 | AllplanAttributes - U-Wert: 0.9; Positionsnummer_Text: U23
Fensteröffnung | H2 Ebene 0 | 1105Fen2005771954 | m² | 0 | Fensterarbeiten | Fensteröffnung | 0 | 0 | NEW | 1105Wa 0000002741 | 0 | RC 1 | 0,51 | AllplanAttributes - U-Wert: 0.9; Positionsnummer_Text: U23
Fensteröffnung | H2 Ebene 0 | 1105Fen2005671309 | m² |  | Metallbau-, Schlosserarbeiten | Fensteröffnung |  |  | NEW
Fensteröffnung | H2 Ebene 0 | 1105Fen2005671310 | m² | 0 | Metallbau-, Schlosserarbeiten | Fensteröffnung | 0 |  | NEW
Fensteröffnung | H2 Ebene 0 | 1105Fen2005671311 | m² | 0 | Metallbau-, Schlosserarbeiten | Fensteröffnung | 0 | 11.25 | NEW
Fensteröffnung | H2 Ebene 0 | 1105Fen2005671312 | m² | 0 | Metallbau-, Schlosserarbeiten | Fensteröffnung | 0 | 11.25 | NEW
Fensteröffnung | H2 Ebene 0 | 1105Fen2005671313 | m² | 0 | Metallbau-, Schlosserarbeiten | Fensteröffnung | 0 | 11.25 | NEW
Fensteröffnung | H2 Ebene 0 | 1105Fen2005674036 | m² |  | Metallbau-, Schlosserarbeiten | Fensteröffnung |  |  | NEW
Fensteröffnung | H2 Ebene 0 | 1105Fen2005674035 | m² | 0 | Metallbau-, Schlosserarbeiten | Fensteröffnung | 0 |  | NEW
Fensteröffnung | H2 Ebene 0 | 1105Fen2005674034 | m² | 0 | Metallbau-, Schlosserarbeiten | Fensteröffnung | 0 | 11.25 | NEW
Fensteröffnung | H2 Ebene 0 | 1105Fen2005674033 | m² | 0 | Metallbau-, Schlosserarbeiten | Fensteröffnung | 0 | 11.25 | NEW
Fensteröffnung | H2 Ebene 0 | 1105Fen2005674032 | m² | 0 | Metallbau-, Schlosserarbeiten | Fensteröffnung | 0 | 11.25 | NEW
Fensteröffnung | H2 Ebene 0 | 1105Fen2005677950 | m² |  | Fensterarbeiten | Fensteröffnung |  | 0 |  | 1105Wa 0000537854 | 0 | RC 1 | 0,51 | AllplanAttributes - Positionsnummer_Text: U23
Fensteröffnung | H2 Ebene 0 | 1105Fen2005677949 | m² | 0 | Fensterarbeiten | Fensteröffnung | 0 | 0 |  | 1105Wa 0000537853 | 0 | RC 1 | 0,51 | AllplanAttributes - Positionsnummer_Text: U23
Fensteröffnung | H2 Ebene 0 | 1105Fen2005677948 | m³ | 0 | Fensterarbeiten | Fensteröffnung | 0 | 0 |  | 1105Wa 0000537852 | 0 | RC 1 | 0,51 | AllplanAttributes - Positionsnummer_Text: U23
Fensteröffnung | H2 Ebene 0 | 1105Fen2005677947 | m³ | 0 | Fensterarbeiten | Fensteröffnung | 0 | 0 |  | 1105Wa 0000537851 | 0 | RC 1 | 0,51 | AllplanAttributes - Positionsnummer_Text: U23
Fensteröffnung | H2 Ebene 0 | 1105Fen2005677946 | m² | 0 | Fensterarbeiten | Fensteröffnung | 0 | 0 | NEW | 1105Wa 0000537850 | 0 | RC 1 | 0,51 | AllplanAttributes - Positionsnummer_Text: U23
Fensteröffnung | H2 Ebene 0 | 1105Fen2005780569 | m² | 0 | Fensterarbeiten | Fensteröffnung | 0 | 0 |  | 1105Wa 0000004538 | 0 | RC 1 | 0,51 | AllplanAttributes - Positionsnummer_Text: U23
Fensteröffnung | H2 Ebene 0 | 1105Fen2005780568 | m³ | 0 | Fensterarbeiten | Fensteröffnung | 0 | 0 |  | 1105Wa 0000004543 | 0 | RC 1 | 0,51 | AllplanAttributes - Positionsnummer_Text: U23
Fensteröffnung | H2 Ebene 0 | 1105Fen2005780567 | m³ | 0 | Fensterarbeiten | Fensteröffnung | 0 | 0 |  | 1105Wa 0000004548 | 0 | RC 1 | 0,51 | AllplanAttributes - Positionsnummer_Text: U23
Fensteröffnung | H2 Ebene 0 | 1105Fen2005780566 | m³ | 0 | Fensterarbeiten | Fensteröffnung | 0 | 0 |  | 1105Wa 0000004553 | 0 | RC 1 | 0,51 | AllplanAttributes - Positionsnummer_Text: U23
Fensteröffnung | H2 Ebene 0 | 1105Fen2005780565 | m² | 0 | Fensterarbeiten | Fensteröffnung | 0 | 0 | NEW | 1105Wa 0000004558 | 0 | RC 1 | 0,51 | AllplanAttributes - Positionsnummer_Text: U23
Fensteröffnung | H2 Ebene 0 | 1105Fen2005780564 | m³ | 0 | Fensterarbeiten | Fensteröffnung | 0 | 0 | NEW | 1105Wa 0000004563 | 0 | RC 1 | 0,51 | AllplanAttributes - Positionsnummer_Text: U23
Fensteröffnung | H2 Ebene 0 | 1105Fen2005780563 | m² | 0 | Fensterarbeiten | Fensteröffnung | 0 | 0 | NEW | 1105Wa 0000004568 | 0 | RC 1 | 0,51 | AllplanAttributes - Positionsnummer_Text: U23
Fensteröffnung | H2 Ebene 0 | 1105Fen2005780562 | m² | 0 | Fensterarbeiten | Fensteröffnung | 0 |  | NEW | 1105Wa 0811441768 | AllplanAttributes - Positionsnummer_Text: U23
Fensteröffnung | H2 Ebene 0 | 1105Fen2005780561 | m² | 0 | Fensterarbeiten | Fensteröffnung | 0 |  | NEW | 1105Wa 0811451476 | AllplanAttributes - Positionsnummer_Text: U23
Fensteröffnung | H2 Ebene 0 | 1105Fen0000041041 | m² |  | Wärmedämm-Verbundsysteme | Fensteröffnung |  | 0 | NEW | 1105Wa 0000000332 | 0 | RC 1 | 0,51 | AllplanAttributes - Material: Fensterelement; Tragendes Bauteil: no; Brandabschnittsdefinierendes Bauteil: no; Positionsnummer_Text: U23
Fensteröffnung | H2 Ebene 0 | 1105Fen0000041125 | m² |  | Wärmedämm-Verbundsysteme | Fensteröffnung |  | 0 | NEW | 1105Wa 0000000332 | 0 | RC 1 | 0,51 | AllplanAttributes - Material: Fensterelement; Tragendes Bauteil: no; Brandabschnittsdefinierendes Bauteil: no; Positionsnummer_Text: U23
Fensteröffnung | H2 Ebene 0 | 1105Fen0000041042 | m³ | 0 | Wärmedämm-Verbundsysteme | Fensteröffnung | 0 | 0 | NEW | 1105Wa 0000000336 | 0 | RC 1 | 0,51 | AllplanAttributes - Material: Fensterelement; Außenliegend: yes; Positionsnummer_Text: U23
Fensteröffnung | H2 Ebene 0 | 1105Fen0000041126 | m³ | 0 | Wärmedämm-Verbundsysteme | Fensteröffnung | 0 | 0 | NEW | 1105Wa 0000000336 | 0 | RC 1 | 0,51 | AllplanAttributes - Material: Fensterelement; Außenliegend: yes; Positionsnummer_Text: U23
Fensteröffnung | H2 Ebene 0 | 1105Fen0000041043 | m³ | 0 | Wärmedämm-Verbundsysteme | Fensteröffnung | 0 | 0 | NEW | 1105Wa 0000000356 | 0 | RC 1 | 0,51 | AllplanAttributes - Positionsnummer_Text: U23
Fensteröffnung | H2 Ebene 0 | 1105Fen0000041127 | m³ | 0 | Wärmedämm-Verbundsysteme | Fensteröffnung | 0 | 0 | NEW | 1105Wa 0000000356 | 0 | RC 1 | 0,51 | AllplanAttributes - Positionsnummer_Text: U23
Fensteröffnung | H2 Ebene 0 | 1105Fen0000041044 | m² | 0 | Wärmedämm-Verbundsysteme | Fensteröffnung | 0 | 0 | NEW | 1105Wa 0000000352 | 0 | RC 1 | 0,51 | AllplanAttributes - Positionsnummer_Text: U23
Fensteröffnung | H2 Ebene 0 | 1105Fen0000041128 | m² | 0 | Wärmedämm-Verbundsysteme | Fensteröffnung | 0 | 0 | NEW | 1105Wa 0000000352 | 0 | RC 1 | 0,51 | AllplanAttributes - Positionsnummer_Text: U23
Fensteröffnung | H2 Ebene 0 | 1105Fen0000041045 | m² | 0 | Wärmedämm-Verbundsysteme | Fensteröffnung | 0 | 0 | NEW | 1105Wa 0000000348 | 0 | RC 1 | 0,51 | AllplanAttributes - Positionsnummer_Text: U23
Fensteröffnung | H2 Ebene 0 | 1105Fen0000041129 | m² | 0 | Wärmedämm-Verbundsysteme | Fensteröffnung | 0 | 0 | NEW | 1105Wa 0000000348 | 0 | RC 1 | 0,51 | AllplanAttributes - Positionsnummer_Text: U23
Fensteröffnung | H2 Ebene 0 | 1105Fen0000041046 | m² | 0 | Wärmedämm-Verbundsysteme | Fensteröffnung | 0 | 0 | NEW | 1105Wa 0000000344 | 0 | RC 1 | 0,51 | AllplanAttributes - Positionsnummer_Text: U23
Fensteröffnung | H2 Ebene 0 | 1105Fen0000041130 | m² | 0 | Wärmedämm-Verbundsysteme | Fensteröffnung | 0 | 0 | NEW | 1105Wa 0000000344 | 0 | RC 1 | 0,51 | AllplanAttributes - Positionsnummer_Text: U23
Fensteröffnung | H2 Ebene 0 | 1105Fen0000041131 | m² | 0 | Wärmedämm-Verbundsysteme | Fensteröffnung | 0 | 0 | NEW | 1105Wa 0000000340 | 0 | RC 1 | 0,51 | AllplanAttributes - Positionsnummer_Text: U23
Fensteröffnung | H2 Ebene 0 | 1105Fen0000041047 | m² | 0 | Wärmedämm-Verbundsysteme | Fensteröffnung | 0 | 0 | NEW | 1105Wa 0000000340 | 0 | RC 1 | 0,51 | AllplanAttributes - Positionsnummer_Text: U23
Fensteröffnung | H2 Ebene 0 | 1105Fen0811560447 | m² |  | Fensterarbeiten | Fensteröffnung |  | 0 |  | 1105Wa 0811560456 | 0 | RC 1 | 0,51 | AllplanAttributes - Positionsnummer_Text: U23
Fensteröffnung | H2 Ebene 0 | 1105Fen0811560446 | m³ | 0 | Fensterarbeiten | Fensteröffnung | 0 | 0 |  | 1105Wa 0811560455 | 0 | RC 1 | 0,51 | AllplanAttributes - Positionsnummer_Text: U23
Fensteröffnung | H2 Ebene 0 | 1105Fen0811560445 | m³ | 0 | Fensterarbeiten | Fensteröffnung | 0 | 0 |  | 1105Wa 0811560454 | 0 | RC 1 | 0,51 | AllplanAttributes - Positionsnummer_Text: U23
Fensteröffnung | H2 Ebene 0 | 1105Fen0811560444 | m³ | 0 | Fensterarbeiten | Fensteröffnung | 0 | 0 |  | 1105Wa 0811560453 | 0 | RC 1 | 0,51 | AllplanAttributes - Positionsnummer_Text: U23
Fensteröffnung | H2 Ebene 0 | 1105Fen0811560443 | m² | 0 | Fensterarbeiten | Fensteröffnung | 0 | 0 | NEW | 1105Wa 0811560452 | 0 | RC 1 | 0,51 | AllplanAttributes - Positionsnummer_Text: U23
Fensteröffnung | H2 Ebene 0 | 1105Fen0811560442 | m³ | 0 | Fensterarbeiten | Fensteröffnung | 0 | 0 | NEW | 1105Wa 0811560451 | 0 | RC 1 | 0,51 | AllplanAttributes - Positionsnummer_Text: U23
Fensteröffnung | H2 Ebene 0 | 1105Fen0811560441 | m² | 0 | Fensterarbeiten | Fensteröffnung | 0 | 0 | NEW | 1105Wa 0811560450 | 0 | RC 1 | 0,51 | AllplanAttributes - Positionsnummer_Text: U23
Fensteröffnung | H2 Ebene 0 | 1105Fen0811560440 | m² | 0 | Fensterarbeiten | Fensteröffnung | 0 |  | NEW | 1105Wa 0811560449 | AllplanAttributes - Positionsnummer_Text: U23
Fensteröffnung | H2 Ebene 0 | 1105Fen0811560439 | m² | 0 | Fensterarbeiten | Fensteröffnung | 0 |  | NEW | 1105Wa 0811560448 | AllplanAttributes - Positionsnummer_Text: U23
Fensteröffnung | H2 Ebene 0 | 1105Fen2005765855 | m² | 0 | Fensterarbeiten | Fensteröffnung | 0 | 0 |  | 1105Wa 0000537854 | 0 | RC 1 | 0,51 | AllplanAttributes - Positionsnummer_Text: U23
Fensteröffnung | H2 Ebene 0 | 1105Fen2005765854 | m² | 0 | Fensterarbeiten | Fensteröffnung | 0 | 0 |  | 1105Wa 0000537853 | 0 | RC 1 | 0,51 | AllplanAttributes - Positionsnummer_Text: U23
Fensteröffnung | H2 Ebene 0 | 1105Fen2005765853 | m³ | 0 | Fensterarbeiten | Fensteröffnung | 0 | 0 |  | 1105Wa 0000537852 | 0 | RC 1 | 0,51 | AllplanAttributes - Positionsnummer_Text: U23
Fensteröffnung | H2 Ebene 0 | 1105Fen2005765852 | m³ | 0 | Fensterarbeiten | Fensteröffnung | 0 | 0 |  | 1105Wa 0000537851 | 0 | RC 1 | 0,51 | AllplanAttributes - Positionsnummer_Text: U23
Fensteröffnung | H2 Ebene 0 | 1105Fen2005765851 | m² | 0 | Fensterarbeiten | Fensteröffnung | 0 | 0 | NEW | 1105Wa 0000537850 | 0 | RC 1 | 0,51 | AllplanAttributes - Positionsnummer_Text: U23
Fensteröffnung | H2 Ebene 0 | 1105Fen2005785673 | m² | 0 | Fensterarbeiten | Fensteröffnung | 0 | 0 |  | 1105Wa 0000003844 | 0 | RC 1 | 0,51 | AllplanAttributes - Positionsnummer_Text: U23
Fensteröffnung | H2 Ebene 0 | 1105Fen0000180381 | m² | 0 | Fensterarbeiten | Fensteröffnung | 0 | 0 |  | 1105Wa 0000180626 | 0 | RC 1 | 0,51 | AllplanAttributes - Positionsnummer_Text: U23
Fensteröffnung | H2 Ebene 0 | 1105Fen2005785204 | m² | 0 | Fensterarbeiten | Fensteröffnung | 0 | 0 |  | 1105Wa 0000180626 | 0 | RC 1 | 0,51 | AllplanAttributes - Positionsnummer_Text: U23
Fensteröffnung | H2 Ebene 0 | 1105Fen2005785366 | m² | 0 | Fensterarbeiten | Fensteröffnung | 0 | 0 |  | 1105Wa 0000180626 | 0 | RC 1 | 0,51 | AllplanAttributes - Positionsnummer_Text: U23
Fensteröffnung | H2 Ebene 0 | 1105Fen2005785448 | m² | 0 | Fensterarbeiten | Fensteröffnung | 0 | 0 |  | 1105Wa 0000180626 | 0 | RC 1 | 0,51 | AllplanAttributes - Positionsnummer_Text: U23
Türöffnung | H2 Ebene 0 | 1105Tür2005786089 | m² | 0 | Trockenbauarbeiten | Türöffnung | 0 | 0 | NEW | 1105Wa 0000180626 | 0 | RC 1 | 0,51 | AllplanAttributes - Codetext: Codetext; Türanschlag: DIN L; Positionsnummer_Text: U23; Pset_OpeningElementCommon - FireExit: no; Reference: Codetext
Fensteröffnung | H2 Ebene 0 | 1105Fen2005785533 | m² | 0 | Fensterarbeiten | Fensteröffnung | 0 | 0 |  | 1105Wa 0000003844 | 0 | RC 1 | 0,51 | AllplanAttributes - Positionsnummer_Text: U23
Fensteröffnung | H2 Ebene 0 | 1105Fen2005785672 | m³ | 0 | Fensterarbeiten | Fensteröffnung | 0 | 0 |  | 1105Wa 0000003834 | 0 | RC 1 | 0,51 | AllplanAttributes - Positionsnummer_Text: U23
Fensteröffnung | H2 Ebene 0 | 1105Fen2005785447 | m³ | 0 | Fensterarbeiten | Fensteröffnung | 0 | 0 |  | 1105Wa 0000180627 | 0 | RC 1 | 0,51 | AllplanAttributes - Positionsnummer_Text: U23
Fensteröffnung | H2 Ebene 0 | 1105Fen2005785365 | m³ | 0 | Fensterarbeiten | Fensteröffnung | 0 | 0 |  | 1105Wa 0000180627 | 0 | RC 1 | 0,51 | AllplanAttributes - Positionsnummer_Text: U23
Fensteröffnung | H2 Ebene 0 | 1105Fen2005785203 | m³ | 0 | Fensterarbeiten | Fensteröffnung | 0 | 0 |  | 1105Wa 0000180627 | 0 | RC 1 | 0,51 | AllplanAttributes - Positionsnummer_Text: U23
Fensteröffnung | H2 Ebene 0 | 1105Fen0000180379 | m³ | 0 | Fensterarbeiten | Fensteröffnung | 0 | 0 |  | 1105Wa 0000180627 | 0 | RC 1 | 0,51 | AllplanAttributes - Positionsnummer_Text: U23
Türöffnung | H2 Ebene 0 | 1105Tür2005786088 | m³ | 0 | Trockenbauarbeiten | Türöffnung | 0 | 0 | NEW | 1105Wa 0000180627 | 0 | RC 1 | 0,51 | AllplanAttributes - ash D_Detailverweis: FSLH2; ash D_Plannummer: D832; Türanschlag: DIN L; Positionsnummer_Text: U23
Fensteröffnung | H2 Ebene 0 | 1105Fen2005785532 | m³ | 0 | Fensterarbeiten | Fensteröffnung | 0 | 0 |  | 1105Wa 0000003834 | 0 | RC 1 | 0,51 | AllplanAttributes - Positionsnummer_Text: U23
Fensteröffnung | H2 Ebene 0 | 1105Fen2005785671 | m³ | 0 | Fensterarbeiten | Fensteröffnung | 0 | 0 |  | 1105Wa 0000003824 | 0 | RC 1 | 0,51 | AllplanAttributes - Positionsnummer_Text: U23
Fensteröffnung | H2 Ebene 0 | 1105Fen2005785446 | m³ | 0 | Fensterarbeiten | Fensteröffnung | 0 | 0 |  | 1105Wa 0000180628 | 0 | RC 1 | 0,51 | AllplanAttributes - Positionsnummer_Text: U23
Fensteröffnung | H2 Ebene 0 | 1105Fen2005785364 | m³ | 0 | Fensterarbeiten | Fensteröffnung | 0 | 0 |  | 1105Wa 0000180628 | 0 | RC 1 | 0,51 | AllplanAttributes - Positionsnummer_Text: U23
Fensteröffnung | H2 Ebene 0 | 1105Fen2005785202 | m³ | 0 | Fensterarbeiten | Fensteröffnung | 0 | 0 |  | 1105Wa 0000180628 | 0 | RC 1 | 0,51 | AllplanAttributes - Positionsnummer_Text: U23
Fensteröffnung | H2 Ebene 0 | 1105Fen0000180377 | m³ | 0 | Fensterarbeiten | Fensteröffnung | 0 | 0 |  | 1105Wa 0000180628 | 0 | RC 1 | 0,51 | AllplanAttributes - Positionsnummer_Text: U23
Türöffnung | H2 Ebene 0 | 1105Tür2005786087 | m³ | 0 | Trockenbauarbeiten | Türöffnung | 0 | 0 | NEW | 1105Wa 0000180628 | 0 | RC 1 | 0,51 | AllplanAttributes - Türanschlag: DIN L; Positionsnummer_Text: U23
Fensteröffnung | H2 Ebene 0 | 1105Fen2005785531 | m³ | 0 | Fensterarbeiten | Fensteröffnung | 0 | 0 |  | 1105Wa 0000003824 | 0 | RC 1 | 0,51 | AllplanAttributes - Positionsnummer_Text: U23
Fensteröffnung | H2 Ebene 0 | 1105Fen2005785670 | m³ | 0 | Fensterarbeiten | Fensteröffnung | 0 | 0 |  | 1105Wa 0000003814 | 0 | RC 1 | 0,51 | AllplanAttributes - Positionsnummer_Text: U23
Fensteröffnung | H2 Ebene 0 | 1105Fen2005785445 | m³ | 0 | Fensterarbeiten | Fensteröffnung | 0 | 0 |  | 1105Wa 0000180629 | 0 | RC 1 | 0,51 | AllplanAttributes - Positionsnummer_Text: U23
Fensteröffnung | H2 Ebene 0 | 1105Fen2005785363 | m³ | 0 | Fensterarbeiten | Fensteröffnung | 0 | 0 |  | 1105Wa 0000180629 | 0 | RC 1 | 0,51 | AllplanAttributes - Positionsnummer_Text: U23
Fensteröffnung | H2 Ebene 0 | 1105Fen2005785201 | m³ | 0 | Fensterarbeiten | Fensteröffnung | 0 | 0 |  | 1105Wa 0000180629 | 0 | RC 1 | 0,51 | AllplanAttributes - Positionsnummer_Text: U23
Fensteröffnung | H2 Ebene 0 | 1105Fen0000180375 | m³ | 0 | Fensterarbeiten | Fensteröffnung | 0 | 0 |  | 1105Wa 0000180629 | 0 | RC 1 | 0,51 | AllplanAttributes - Positionsnummer_Text: U23
Türöffnung | H2 Ebene 0 | 1105Tür2005786086 | m³ | 0 | Trockenbauarbeiten | Türöffnung | 0 | 0 | NEW | 1105Wa 0000180629 | 0 | RC 1 | 0,51 | AllplanAttributes - Türanschlag: DIN L; Positionsnummer_Text: U23
Fensteröffnung | H2 Ebene 0 | 1105Fen2005785530 | m³ | 0 | Fensterarbeiten | Fensteröffnung | 0 | 0 |  | 1105Wa 0000003814 | 0 | RC 1 | 0,51 | AllplanAttributes - Positionsnummer_Text: U23
Fensteröffnung | H2 Ebene 0 | 1105Fen2005785669 | m² | 0 | Fensterarbeiten | Fensteröffnung | 0 | 0 | NEW | 1105Wa 0000003804 | 0 | RC 1 | 0,51 | AllplanAttributes - Positionsnummer_Text: U23
Fensteröffnung | H2 Ebene 0 | 1105Fen2005785444 | m² | 0 | Fensterarbeiten | Fensteröffnung | 0 | 0 | NEW | 1105Wa 0000180630 | 0 | RC 1 | 0,51 | AllplanAttributes - Positionsnummer_Text: U23
Fensteröffnung | H2 Ebene 0 | 1105Fen2005785362 | m² | 0 | Fensterarbeiten | Fensteröffnung | 0 | 0 | NEW | 1105Wa 0000180630 | 0 | RC 1 | 0,51 | AllplanAttributes - Positionsnummer_Text: U23
Fensteröffnung | H2 Ebene 0 | 1105Fen2005785200 | m² | 0 | Fensterarbeiten | Fensteröffnung | 0 | 0 | NEW | 1105Wa 0000180630 | 0 | RC 1 | 0,51 | AllplanAttributes - Positionsnummer_Text: U23
Fensteröffnung | H2 Ebene 0 | 1105Fen0000180373 | m² | 0 | Fensterarbeiten | Fensteröffnung | 0 | 0 | NEW | 1105Wa 0000180630 | 0 | RC 1 | 0,51 | AllplanAttributes - Positionsnummer_Text: U23
Türöffnung | H2 Ebene 0 | 1105Tür2005786085 | m² | 0 | Trockenbauarbeiten | Türöffnung | 0 | 0 | NEW | 1105Wa 0000180630 | 0 | RC 1 | 0,51 | AllplanAttributes - Türanschlag: DIN L; Positionsnummer_Text: U23
Fensteröffnung | H2 Ebene 0 | 1105Fen2005785529 | m² | 0 | Fensterarbeiten | Fensteröffnung | 0 | 0 | NEW | 1105Wa 0000003804 | 0 | RC 1 | 0,51 | AllplanAttributes - Positionsnummer_Text: U23
Fensteröffnung | H2 Ebene 0 | 1105Fen2005785668 | m² | 0 | Fensterarbeiten | Fensteröffnung | 0 | 0 | NEW | 1105Wa 0000003794 | 0 | RC 1 | 0,51 | AllplanAttributes - Positionsnummer_Text: U23
Fensteröffnung | H2 Ebene 0 | 1105Fen2005785443 | m² | 0 | Fensterarbeiten | Fensteröffnung | 0 | 0 | NEW | 1105Wa 0000180631 | 0 | RC 1 | 0,51 | AllplanAttributes - Positionsnummer_Text: U23
Fensteröffnung | H2 Ebene 0 | 1105Fen2005785361 | m² | 0 | Fensterarbeiten | Fensteröffnung | 0 | 0 | NEW | 1105Wa 0000180631 | 0 | RC 1 | 0,51 | AllplanAttributes - Positionsnummer_Text: U23
Fensteröffnung | H2 Ebene 0 | 1105Fen2005785199 | m² | 0 | Fensterarbeiten | Fensteröffnung | 0 | 0 | NEW | 1105Wa 0000180631 | 0 | RC 1 | 0,51 | AllplanAttributes - Positionsnummer_Text: U23
Fensteröffnung | H2 Ebene 0 | 1105Fen0000180371 | m² | 0 | Fensterarbeiten | Fensteröffnung | 0 | 0 | NEW | 1105Wa 0000180631 | 0 | RC 1 | 0,51 | AllplanAttributes - Positionsnummer_Text: U23
Türöffnung | H2 Ebene 0 | 1105Tür2005786084 | m² | 0 | Trockenbauarbeiten | Türöffnung | 0 | 0 | NEW | 1105Wa 0000180631 | 0 | RC 1 | 0,51 | AllplanAttributes - Türanschlag: DIN L; Positionsnummer_Text: U23
Fensteröffnung | H2 Ebene 0 | 1105Fen2005785528 | m² | 0 | Fensterarbeiten | Fensteröffnung | 0 | 0 | NEW | 1105Wa 0000003794 | 0 | RC 1 | 0,51 | AllplanAttributes - Positionsnummer_Text: U23
Fensteröffnung | H2 Ebene 0 | 1105Fen2005785667 | m² | 0 | Fensterarbeiten | Fensteröffnung | 0 | 0 | NEW | 1105Wa 0000003784 | 0 | RC 1 | 0,51 | AllplanAttributes - Positionsnummer_Text: U23
Fensteröffnung | H2 Ebene 0 | 1105Fen2005785442 | m² | 0 | Fensterarbeiten | Fensteröffnung | 0 | 0 | NEW | 1105Wa 0000180632 | 0 | RC 1 | 0,51 | AllplanAttributes - Positionsnummer_Text: U23
Fensteröffnung | H2 Ebene 0 | 1105Fen2005785360 | m² | 0 | Fensterarbeiten | Fensteröffnung | 0 | 0 | NEW | 1105Wa 0000180632 | 0 | RC 1 | 0,51 | AllplanAttributes - Positionsnummer_Text: U23
Fensteröffnung | H2 Ebene 0 | 1105Fen2005785198 | m² | 0 | Fensterarbeiten | Fensteröffnung | 0 | 0 | NEW | 1105Wa 0000180632 | 0 | RC 1 | 0,51 | AllplanAttributes - Positionsnummer_Text: U23
Fensteröffnung | H2 Ebene 0 | 1105Fen0000180369 | m² | 0 | Fensterarbeiten | Fensteröffnung | 0 | 0 | NEW | 1105Wa 0000180632 | 0 | RC 1 | 0,51 | AllplanAttributes - Positionsnummer_Text: U23
Türöffnung | H2 Ebene 0 | 1105Tür2005786083 | m² | 0 | Trockenbauarbeiten | Türöffnung | 0 | 0 | NEW | 1105Wa 0000180632 | 0 | RC 1 | 0,51 | AllplanAttributes - Türanschlag: DIN L; Positionsnummer_Text: U23
Fensteröffnung | H2 Ebene 0 | 1105Fen2005785527 | m² | 0 | Fensterarbeiten | Fensteröffnung | 0 | 0 | NEW | 1105Wa 0000003784 | 0 | RC 1 | 0,51 | AllplanAttributes - Positionsnummer_Text: U23
Fensteröffnung | H2 Ebene 0 | 1105Fen2005785666 | m² | 0 | Fensterarbeiten | Fensteröffnung | 0 |  | NEW | 1105Wa 0811580073 | AllplanAttributes - Positionsnummer_Text: U23
Fensteröffnung | H2 Ebene 0 | 1105Fen2005785441 | m² | 0 | Fensterarbeiten | Fensteröffnung | 0 |  | NEW | 1105Wa 0811580073 | AllplanAttributes - Positionsnummer_Text: U23
Fensteröffnung | H2 Ebene 0 | 1105Fen2005785359 | m² | 0 | Fensterarbeiten | Fensteröffnung | 0 |  | NEW | 1105Wa 0811580073 | AllplanAttributes - Positionsnummer_Text: U23
Fensteröffnung | H2 Ebene 0 | 1105Fen2005785197 | m² | 0 | Fensterarbeiten | Fensteröffnung | 0 |  | NEW | 1105Wa 0811580073 | AllplanAttributes - Positionsnummer_Text: U23
Fensteröffnung | H2 Ebene 0 | 1105Fen0811580570 | m² | 0 | Fensterarbeiten | Fensteröffnung | 0 |  | NEW | 1105Wa 0811580073 | AllplanAttributes - Positionsnummer_Text: U23
Türöffnung | H2 Ebene 0 | 1105Tür2005786082 | m² | 0 | Trockenbauarbeiten | Türöffnung | 0 |  | NEW | 1105Wa 0811580073 | AllplanAttributes - Türanschlag: DIN L; Positionsnummer_Text: U23
Fensteröffnung | H2 Ebene 0 | 1105Fen2005785526 | m² | 0 | Fensterarbeiten | Fensteröffnung | 0 |  | NEW | 1105Wa 0811580073 | AllplanAttributes - Positionsnummer_Text: U23
Fensteröffnung | H2 Ebene 0 | 1105Fen2005776982 | m² | 0 | Fensterarbeiten | Fensteröffnung | 0 | 0 |  | 1105Wa 0000003947 | 0 | RC 1 | 0,51 | AllplanAttributes - Positionsnummer_Text: U23
Fensteröffnung | H2 Ebene 0 | 1105Fen2005776865 | m² | 0 | Fensterarbeiten | Fensteröffnung | 0 | 0 |  | 1105Wa 0000003947 | 0 | RC 1 | 0,51 | AllplanAttributes - Positionsnummer_Text: U23
Fensteröffnung | H2 Ebene 0 | 1105Fen2005776703 | m² | 0 | Fensterarbeiten | Fensteröffnung | 0 | 0 |  | 1105Wa 0000003947 | 0 | RC 1 | 0,51 | AllplanAttributes - Positionsnummer_Text: U23
Türöffnung | H2 Ebene 0 | 1105Tür0000085260 | m² |  | Trockenbauarbeiten | Türöffnung |  | 0 | NEW | 1105Wa 0000003877 | 0 | RC 1 | 0,51 | AllplanAttributes - Codetext: Codetext; Türanschlag: DIN R; Positionsnummer_Text: U23; Pset_OpeningElementCommon - FireExit: no; Reference: Codetext
Fensteröffnung | H2 Ebene 0 | 1105Fen2005776702 | m³ | 0 | Fensterarbeiten | Fensteröffnung | 0 | 0 |  | 1105Wa 0000003957 | 0 | RC 1 | 0,51 | AllplanAttributes - Positionsnummer_Text: U23
Fensteröffnung | H2 Ebene 0 | 1105Fen2005776864 | m³ | 0 | Fensterarbeiten | Fensteröffnung | 0 | 0 |  | 1105Wa 0000003957 | 0 | RC 1 | 0,51 | AllplanAttributes - Positionsnummer_Text: U23
Fensteröffnung | H2 Ebene 0 | 1105Fen2005776981 | m³ | 0 | Fensterarbeiten | Fensteröffnung | 0 | 0 |  | 1105Wa 0000003957 | 0 | RC 1 | 0,51 | AllplanAttributes - Positionsnummer_Text: U23
Türöffnung | H2 Ebene 0 | 1105Tür0000085262 | m³ | 0 | Trockenbauarbeiten | Türöffnung | 0 | 0 | NEW | 1105Wa 0000003882 | 0 | RC 1 | 0,51 | AllplanAttributes - Türanschlag: DIN R; Positionsnummer_Text: U23
Fensteröffnung | H2 Ebene 0 | 1105Fen2005776701 | m³ | 0 | Fensterarbeiten | Fensteröffnung | 0 | 0 |  | 1105Wa 0000003966 | 0 | RC 1 | 0,51 | AllplanAttributes - Positionsnummer_Text: U23
Fensteröffnung | H2 Ebene 0 | 1105Fen2005776863 | m³ | 0 | Fensterarbeiten | Fensteröffnung | 0 | 0 |  | 1105Wa 0000003966 | 0 | RC 1 | 0,51 | AllplanAttributes - Positionsnummer_Text: U23
Fensteröffnung | H2 Ebene 0 | 1105Fen2005776980 | m³ | 0 | Fensterarbeiten | Fensteröffnung | 0 | 0 |  | 1105Wa 0000003966 | 0 | RC 1 | 0,51 | AllplanAttributes - Positionsnummer_Text: U23
Türöffnung | H2 Ebene 0 | 1105Tür0000085264 | m³ | 0 | Trockenbauarbeiten | Türöffnung | 0 | 0 | NEW | 1105Wa 0000003886 | 0 | RC 1 | 0,51 | AllplanAttributes - Türanschlag: DIN R; Positionsnummer_Text: U23
Fensteröffnung | H2 Ebene 0 | 1105Fen2005776700 | m³ | 0 | Fensterarbeiten | Fensteröffnung | 0 | 0 |  | 1105Wa 0000003976 | 0 | RC 1 | 0,51 | AllplanAttributes - Positionsnummer_Text: U23
Fensteröffnung | H2 Ebene 0 | 1105Fen2005776862 | m³ | 0 | Fensterarbeiten | Fensteröffnung | 0 | 0 |  | 1105Wa 0000003976 | 0 | RC 1 | 0,51 | AllplanAttributes - Positionsnummer_Text: U23
Fensteröffnung | H2 Ebene 0 | 1105Fen2005776979 | m³ | 0 | Fensterarbeiten | Fensteröffnung | 0 | 0 |  | 1105Wa 0000003976 | 0 | RC 1 | 0,51 | AllplanAttributes - Positionsnummer_Text: U23
Türöffnung | H2 Ebene 0 | 1105Tür0000085266 | m³ | 0 | Trockenbauarbeiten | Türöffnung | 0 | 0 | NEW | 1105Wa 0000003891 | 0 | RC 1 | 0,51 | AllplanAttributes - Türanschlag: DIN R; Positionsnummer_Text: U23
Fensteröffnung | H2 Ebene 0 | 1105Fen2005776699 | m² | 0 | Fensterarbeiten | Fensteröffnung | 0 | 0 | NEW | 1105Wa 0000003986 | 0 | RC 1 | 0,51 | AllplanAttributes - Positionsnummer_Text: U23
Fensteröffnung | H2 Ebene 0 | 1105Fen2005776861 | m² | 0 | Fensterarbeiten | Fensteröffnung | 0 | 0 | NEW | 1105Wa 0000003986 | 0 | RC 1 | 0,51 | AllplanAttributes - Positionsnummer_Text: U23
Fensteröffnung | H2 Ebene 0 | 1105Fen2005776978 | m² | 0 | Fensterarbeiten | Fensteröffnung | 0 | 0 | NEW | 1105Wa 0000003986 | 0 | RC 1 | 0,51 | AllplanAttributes - Positionsnummer_Text: U23
Türöffnung | H2 Ebene 0 | 1105Tür0000085268 | m² | 0 | Trockenbauarbeiten | Türöffnung | 0 | 0 | NEW | 1105Wa 0000003896 | 0 | RC 1 | 0,51 | AllplanAttributes - Türanschlag: DIN R; Positionsnummer_Text: U23
Fensteröffnung | H2 Ebene 0 | 1105Fen2005776698 | m² | 0 | Fensterarbeiten | Fensteröffnung | 0 | 0 | NEW | 1105Wa 0000003996 | 0 | RC 1 | 0,51 | AllplanAttributes - Positionsnummer_Text: U23
Fensteröffnung | H2 Ebene 0 | 1105Fen2005776860 | m² | 0 | Fensterarbeiten | Fensteröffnung | 0 | 0 | NEW | 1105Wa 0000003996 | 0 | RC 1 | 0,51 | AllplanAttributes - Positionsnummer_Text: U23
Fensteröffnung | H2 Ebene 0 | 1105Fen2005776977 | m² | 0 | Fensterarbeiten | Fensteröffnung | 0 | 0 | NEW | 1105Wa 0000003996 | 0 | RC 1 | 0,51 | AllplanAttributes - Positionsnummer_Text: U23
Türöffnung | H2 Ebene 0 | 1105Tür0000085270 | m² | 0 | Trockenbauarbeiten | Türöffnung | 0 | 0 | NEW | 1105Wa 0000003901 | 0 | RC 1 | 0,51 | AllplanAttributes - Türanschlag: DIN R; Positionsnummer_Text: U23
Fensteröffnung | H2 Ebene 0 | 1105Fen2005776697 | m² | 0 | Fensterarbeiten | Fensteröffnung | 0 | 0 | NEW | 1105Wa 0000004006 | 0 | RC 1 | 0,51 | AllplanAttributes - Positionsnummer_Text: U23
Fensteröffnung | H2 Ebene 0 | 1105Fen2005776859 | m² | 0 | Fensterarbeiten | Fensteröffnung | 0 | 0 | NEW | 1105Wa 0000004006 | 0 | RC 1 | 0,51 | AllplanAttributes - Positionsnummer_Text: U23
Fensteröffnung | H2 Ebene 0 | 1105Fen2005776976 | m² | 0 | Fensterarbeiten | Fensteröffnung | 0 | 0 | NEW | 1105Wa 0000004006 | 0 | RC 1 | 0,51 | AllplanAttributes - Positionsnummer_Text: U23
Türöffnung | H2 Ebene 0 | 1105Tür0000085272 | m² | 0 | Trockenbauarbeiten | Türöffnung | 0 | 0 | NEW | 1105Wa 0000003906 | 0 | RC 1 | 0,51 | AllplanAttributes - Türanschlag: DIN R; Positionsnummer_Text: U23
Fensteröffnung | H2 Ebene 0 | 1105Fen2005776696 | m² | 0 | Fensterarbeiten | Fensteröffnung | 0 |  | NEW
Fensteröffnung | H2 Ebene 0 | 1105Fen2005776858 | m² | 0 | Fensterarbeiten | Fensteröffnung | 0 |  | NEW
Fensteröffnung | H2 Ebene 0 | 1105Fen2005776975 | m² | 0 | Fensterarbeiten | Fensteröffnung | 0 |  | NEW
Türöffnung | H2 Ebene 0 | 1105Tür0811579045 | m² | 0 | Trockenbauarbeiten | Türöffnung | 0 |  | NEW | 1105Wa 0811578750 | AllplanAttributes - Türanschlag: DIN R; Positionsnummer_Text: U23
Fensteröffnung | H2 Ebene 0 | 1105Fen0000041083 | m² |  | Wärmedämm-Verbundsysteme | Fensteröffnung |  | 0 | NEW | 1105Wa 0000001868 | 0 | RC 1 | 0,51 | AllplanAttributes - Material: Fensterelement; Tragendes Bauteil: no; Brandabschnittsdefinierendes Bauteil: no; Positionsnummer_Text: U23
Fensteröffnung | H2 Ebene 0 | 1105Fen0000041084 | m³ | 0 | Wärmedämm-Verbundsysteme | Fensteröffnung | 0 | 0 | NEW | 1105Wa 0000001872 | 0 | RC 1 | 0,51 | AllplanAttributes - Material: Fensterelement; Außenliegend: yes; Positionsnummer_Text: U23
Fensteröffnung | H2 Ebene 0 | 1105Fen0000041085 | m³ | 0 | Wärmedämm-Verbundsysteme | Fensteröffnung | 0 | 0 | NEW | 1105Wa 0000001876 | 0 | RC 1 | 0,51 | AllplanAttributes - Positionsnummer_Text: U23
Fensteröffnung | H2 Ebene 0 | 1105Fen0000041086 | m² | 0 | Wärmedämm-Verbundsysteme | Fensteröffnung | 0 | 0 | NEW | 1105Wa 0000001880 | 0 | RC 1 | 0,51 | AllplanAttributes - Positionsnummer_Text: U23
Fensteröffnung | H2 Ebene 0 | 1105Fen0000041087 | m² | 0 | Wärmedämm-Verbundsysteme | Fensteröffnung | 0 | 0 | NEW | 1105Wa 0000001884 | 0 | RC 1 | 0,51 | AllplanAttributes - Positionsnummer_Text: U23
Fensteröffnung | H2 Ebene 0 | 1105Fen0000041088 | m² | 0 | Wärmedämm-Verbundsysteme | Fensteröffnung | 0 | 0 | NEW | 1105Wa 0000001888 | 0 | RC 1 | 0,51 | AllplanAttributes - Positionsnummer_Text: U23
Fensteröffnung | H2 Ebene 0 | 1105Fen0000041089 | m² | 0 | Wärmedämm-Verbundsysteme | Fensteröffnung | 0 | 0 | NEW | 1105Wa 0000001892 | 0 | RC 1 | 0,51 | AllplanAttributes - Positionsnummer_Text: U23
Fensteröffnung | H2 Ebene 0 | 1105Fen0811559646 | m² |  | Wärmedämm-Verbundsysteme | Fensteröffnung |  | 0 | NEW | 1105Wa 0811559664 | 0 | RC 1 | 0,51 | AllplanAttributes - Material: Fensterelement; Tragendes Bauteil: no; Brandabschnittsdefinierendes Bauteil: no; Positionsnummer_Text: U23
Fensteröffnung | H2 Ebene 0 | 1105Fen0811559648 | m² |  | Wärmedämm-Verbundsysteme | Fensteröffnung |  | 0 | NEW | 1105Wa 0811559664 | 0 | RC 1 | 0,51 | AllplanAttributes - Material: Fensterelement; Tragendes Bauteil: no; Brandabschnittsdefinierendes Bauteil: no; Positionsnummer_Text: U23
Fensteröffnung | H2 Ebene 0 | 1105Fen0811559647 | m³ | 0 | Wärmedämm-Verbundsysteme | Fensteröffnung | 0 | 0 | NEW | 1105Wa 0811559663 | 0 | RC 1 | 0,51 | AllplanAttributes - Material: Fensterelement; Außenliegend: yes; Positionsnummer_Text: U23
Fensteröffnung | H2 Ebene 0 | 1105Fen0811559649 | m³ | 0 | Wärmedämm-Verbundsysteme | Fensteröffnung | 0 | 0 | NEW | 1105Wa 0811559663 | 0 | RC 1 | 0,51 | AllplanAttributes - Material: Fensterelement; Außenliegend: yes; Positionsnummer_Text: U23
Fensteröffnung | H2 Ebene 0 | 1105Fen0811559644 | m³ | 0 | Wärmedämm-Verbundsysteme | Fensteröffnung | 0 | 0 | NEW | 1105Wa 0811559662 | 0 | RC 1 | 0,51 | AllplanAttributes - Positionsnummer_Text: U23
Fensteröffnung | H2 Ebene 0 | 1105Fen0811559645 | m³ | 0 | Wärmedämm-Verbundsysteme | Fensteröffnung | 0 | 0 | NEW | 1105Wa 0811559662 | 0 | RC 1 | 0,51 | AllplanAttributes - Positionsnummer_Text: U23
Fensteröffnung | H2 Ebene 0 | 1105Fen0811559650 | m² | 0 | Wärmedämm-Verbundsysteme | Fensteröffnung | 0 | 0 | NEW | 1105Wa 0811559661 | 0 | RC 1 | 0,51 | AllplanAttributes - Positionsnummer_Text: U23
Fensteröffnung | H2 Ebene 0 | 1105Fen0811559654 | m² | 0 | Wärmedämm-Verbundsysteme | Fensteröffnung | 0 | 0 | NEW | 1105Wa 0811559661 | 0 | RC 1 | 0,51 | AllplanAttributes - Positionsnummer_Text: U23
Fensteröffnung | H2 Ebene 0 | 1105Fen0811559651 | m² | 0 | Wärmedämm-Verbundsysteme | Fensteröffnung | 0 | 0 | NEW | 1105Wa 0811559660 | 0 | RC 1 | 0,51 | AllplanAttributes - Positionsnummer_Text: U23
Fensteröffnung | H2 Ebene 0 | 1105Fen0811559655 | m² | 0 | Wärmedämm-Verbundsysteme | Fensteröffnung | 0 | 0 | NEW | 1105Wa 0811559660 | 0 | RC 1 | 0,51 | AllplanAttributes - Positionsnummer_Text: U23
Fensteröffnung | H2 Ebene 0 | 1105Fen0811559652 | m² | 0 | Wärmedämm-Verbundsysteme | Fensteröffnung | 0 | 0 | NEW | 1105Wa 0811559659 | 0 | RC 1 | 0,51 | AllplanAttributes - Positionsnummer_Text: U23
Fensteröffnung | H2 Ebene 0 | 1105Fen0811559656 | m² | 0 | Wärmedämm-Verbundsysteme | Fensteröffnung | 0 | 0 | NEW | 1105Wa 0811559659 | 0 | RC 1 | 0,51 | AllplanAttributes - Positionsnummer_Text: U23
Fensteröffnung | H2 Ebene 0 | 1105Fen0811559653 | m² | 0 | Wärmedämm-Verbundsysteme | Fensteröffnung | 0 | 0 | NEW | 1105Wa 0811559658 | 0 | RC 1 | 0,51 | AllplanAttributes - Positionsnummer_Text: U23
Fensteröffnung | H2 Ebene 0 | 1105Fen0811559657 | m² | 0 | Wärmedämm-Verbundsysteme | Fensteröffnung | 0 | 0 | NEW | 1105Wa 0811559658 | 0 | RC 1 | 0,51 | AllplanAttributes - Positionsnummer_Text: U23
Türöffnung | H2 Ebene 0 | 1105Tür0000034969 | m² |  | Zimmer- und Holzbauarbeiten | Türöffnung |  | 0 | NEW | 1105Wa 0000034791 | 0 | RC 1 | 0,51 | AllplanAttributes - ash D_Detailverweis: FS TRH3; ash D_Plannummer: D1530; U-Wert: 0.9; Türanschlag: DIN L; ash T_Feststellanlage (FSA): -; Positionsnummer_Text: U23
Türöffnung | H2 Ebene 0 | 1105Tür0000034968 | m³ | 0 | Zimmer- und Holzbauarbeiten | Türöffnung | 0 | 0 | NEW | 1105Wa 0000034790 | 0 | RC 1 | 0,51 | AllplanAttributes - U-Wert: 0.9; Türanschlag: DIN L; ash T_Feststellanlage (FSA): -; Positionsnummer_Text: U23
Türöffnung | H2 Ebene 0 | 1105Tür0000034967 | m² | 0 | Zimmer- und Holzbauarbeiten | Türöffnung | 0 | 0 | NEW | 1105Wa 0000034789 | 0 | RC 1 | 0,51 | AllplanAttributes - U-Wert: 0.9; Türanschlag: DIN L; ash T_Feststellanlage (FSA): -; Positionsnummer_Text: U23; ash T_Türschließer: OTS; ash T_Schlossfunktion: SVP; ash T_Beschlag: KD
Türöffnung | H2 Ebene 0 | 1105Tür0000034966 | m² | 0 | Zimmer- und Holzbauarbeiten | Türöffnung | 0 | 0 | NEW | 1105Wa 0000034788 | 0 | RC 1 | 0,51 | AllplanAttributes - U-Wert: 0.9; Türanschlag: DIN L; ash T_Feststellanlage (FSA): -; Positionsnummer_Text: U23
Türöffnung | H2 Ebene 0 | 1105Tür0000034965 | m² | 0 | Zimmer- und Holzbauarbeiten | Türöffnung | 0 | 0 | NEW | 1105Wa 0000034787 | 0 | RC 1 | 0,51 | AllplanAttributes - U-Wert: 0.9; Türanschlag: DIN L; ash T_Feststellanlage (FSA): -; Positionsnummer_Text: U23
Türöffnung | H2 Ebene 0 | 1105Tür0000158504 | m² | 0 | Zimmer- und Holzbauarbeiten | Türöffnung | 0 |  | NEW | 1105Wa 0000158461 | 0 | RC 1 | 0,51 | AllplanAttributes - U-Wert: 0.9; Türanschlag: DIN L; Positionsnummer_Text: U23
Türöffnung | H2 Ebene 0 | 1105Tür0000034310 | m² |  | Zimmer- und Holzbauarbeiten | Türöffnung |  | 0 | NEW | 1105Wa 0000003016 | 0 | RC 1 | 0,51 | AllplanAttributes - Türanschlag: DIN L; ash T_Feststellanlage (FSA): -; Positionsnummer_Text: U23
Türöffnung | H2 Ebene 0 | 1105Tür0000034309 | m³ | 0 | Zimmer- und Holzbauarbeiten | Türöffnung | 0 | 0 | NEW | 1105Wa 0000002967 | 0 | RC 1 | 0,51 | AllplanAttributes - Türanschlag: DIN L; ash T_Feststellanlage (FSA): -; Positionsnummer_Text: U23
Türöffnung | H2 Ebene 0 | 1105Tür0000034308 | m² | 0 | Zimmer- und Holzbauarbeiten | Türöffnung | 0 | 0 | NEW | 1105Wa 0000002971 | 0 | RC 1 | 0,51 | AllplanAttributes - Türanschlag: DIN L; ash T_Feststellanlage (FSA): -; Positionsnummer_Text: U23
Türöffnung | H2 Ebene 0 | 1105Tür0000034307 | m² | 0 | Zimmer- und Holzbauarbeiten | Türöffnung | 0 | 0 | NEW | 1105Wa 0000002975 | 0 | RC 1 | 0,51 | AllplanAttributes - Türanschlag: DIN L; ash T_Feststellanlage (FSA): -; Positionsnummer_Text: U23
Türöffnung | H2 Ebene 0 | 1105Tür0000034306 | m² | 0 | Zimmer- und Holzbauarbeiten | Türöffnung | 0 | 0 | NEW | 1105Wa 0000002979 | 0 | RC 1 | 0,51 | AllplanAttributes - Türanschlag: DIN L; ash T_Feststellanlage (FSA): -; Positionsnummer_Text: U23
Türöffnung | H2 Ebene 0 | 1105Tür0000160689 | m² | 0 | Zimmer- und Holzbauarbeiten | Türöffnung | 0 |  | NEW | 1105Wa 0000160617 | 0 | RC 1 | 0,51 | AllplanAttributes - Türanschlag: DIN L; Positionsnummer_Text: U23
Fensteröffnung | H2 Ebene 0 | 1105Fen0000538318 | m² |  | Fensterarbeiten | Fensteröffnung |  | 0 |  | 1105Wa 0000538036 | 0 | RC 1 | 0,51 | AllplanAttributes - Positionsnummer_Text: U23
Fensteröffnung | H2 Ebene 0 | 1105Fen0000538317 | m² | 0 | Fensterarbeiten | Fensteröffnung | 0 | 0 |  | 1105Wa 0000538037 | 0 | RC 1 | 0,51 | AllplanAttributes - Positionsnummer_Text: U23
Fensteröffnung | H2 Ebene 0 | 1105Fen0000538316 | m³ | 0 | Fensterarbeiten | Fensteröffnung | 0 | 0 |  | 1105Wa 0000538038 | 0 | RC 1 | 0,51 | AllplanAttributes - Positionsnummer_Text: U23
Fensteröffnung | H2 Ebene 0 | 1105Fen0000538315 | m² | 0 | Fensterarbeiten | Fensteröffnung | 0 | 0 |  | 1105Wa 0000538039 | 0 | RC 1 | 0,51 | AllplanAttributes - Positionsnummer_Text: U23
Fensteröffnung | H2 Ebene 0 | 1105Fen0000538314 | m² | 0 | Fensterarbeiten | Fensteröffnung | 0 | 0 | NEW | 1105Wa 0000538040 | 0 | RC 1 | 0,51 | AllplanAttributes - Positionsnummer_Text: U23
Fensteröffnung | H2 Ebene 0 | 1105Fen0000538313 | m² | 0 | Fensterarbeiten | Fensteröffnung | 0 | 0 | NEW | 1105Wa 0000538041 | 0 | RC 1 | 0,51 | AllplanAttributes - Positionsnummer_Text: U23
Fensteröffnung | H2 Ebene 0 | 1105Fen2005694857 | m² | 0 | Fensterarbeiten | Fensteröffnung | 0 |  | NEW
Türöffnung | H2 Ebene 0 | 1105Tür0000035964 | m² |  | Zimmer- und Holzbauarbeiten | Türöffnung |  | 0 | NEW | 1105Wa 0000035816 | 0 | RC 1 | 0,51 | AllplanAttributes - Türanschlag: DIN L; ash T_Feststellanlage (FSA): -; Positionsnummer_Text: U23
Türöffnung | H2 Ebene 0 | 1105Tür0000035963 | m³ | 0 | Zimmer- und Holzbauarbeiten | Türöffnung | 0 | 0 | NEW | 1105Wa 0000035817 | 0 | RC 1 | 0,51 | AllplanAttributes - Türanschlag: DIN L; ash T_Feststellanlage (FSA): -; Positionsnummer_Text: U23
Türöffnung | H2 Ebene 0 | 1105Tür0000035962 | m² | 0 | Zimmer- und Holzbauarbeiten | Türöffnung | 0 | 0 | NEW | 1105Wa 0000035818 | 0 | RC 1 | 0,51 | AllplanAttributes - Türanschlag: DIN L; ash T_Feststellanlage (FSA): -; Positionsnummer_Text: U23
Türöffnung | H2 Ebene 0 | 1105Tür0000035961 | m² | 0 | Zimmer- und Holzbauarbeiten | Türöffnung | 0 | 0 | NEW | 1105Wa 0000035819 | 0 | RC 1 | 0,51 | AllplanAttributes - Türanschlag: DIN L; ash T_Feststellanlage (FSA): -; Positionsnummer_Text: U23
Türöffnung | H2 Ebene 0 | 1105Tür0000035960 | m² | 0 | Zimmer- und Holzbauarbeiten | Türöffnung | 0 | 0 | NEW | 1105Wa 0000035820 | 0 | RC 1 | 0,51 | AllplanAttributes - Türanschlag: DIN L; ash T_Feststellanlage (FSA): -; Positionsnummer_Text: U23
Türöffnung | H2 Ebene 0 | 1105Tür0000159910 | m² | 0 | Zimmer- und Holzbauarbeiten | Türöffnung | 0 |  | NEW | 1105Wa 0000159880 | 0 | RC 1 | 0,51 | AllplanAttributes - Türanschlag: DIN L; Positionsnummer_Text: U23
Türöffnung | H2 Ebene 0 | 1113Tür0812440433 | m² |  | Trockenbauarbeiten | Türöffnung |  | 0 | NEW | 1113Wa 0812443609 | AllplanAttributes - Bezeichnung: Türöffnung; Codetext: Codetext; Türanschlag: -; Attributset-Objekt: OpeningElement; W_Deckenanschluss: Gleitender Deckenanschluss Fall 01; Positionsnummer_Text: S68; Ortscode_Geschoßbezeichnung: E00; Pset_OpeningElementCommon - FireExit: no; Reference: Codetext
Türöffnung | H2 Ebene 0 | 1113Tür0812436414 | m² |  | Trockenbauarbeiten | Türöffnung |  | 0 | NEW | 1113Wa 0812437641 | AllplanAttributes - Bezeichnung: Türöffnung; Codetext: Codetext; Türanschlag: -; Attributset-Objekt: OpeningElement; W_Deckenanschluss: Gleitender Deckenanschluss Fall 01; Positionsnummer_Text: S68; Ortscode_Geschoßbezeichnung: E00; Pset_OpeningElementCommon - FireExit: no; Reference: Codetext
Türöffnung | H2 Ebene 0 | 1113Tür0812549299 | m² |  | Trockenbauarbeiten | Türöffnung |  | 0 | NEW | 1113Wa 0812549302 | EI2 30 | AllplanAttributes - Codetext: Codetext; Türanschlag: -; Attributset-Objekt: OpeningElement; Rauchschutz: yes; Selbstschließend: yes; ash T_Zulage Schachttür: no; ash T_Dichtschließend: no; ash T_Feststellanlage (FSA): -; ash T_nicht abschließbar: no; W_Deckenanschluss: Gleitender Deckenanschluss Fall 01; Positionsnummer_Text: S68; Ortscode_Geschoßbezeichnung: E00; Pset_OpeningElementCommon - FireExit: no; Reference: Codetext
Türöffnung | H2 Ebene 0 | 1113Tür0812549649 | m² |  | Trockenbauarbeiten | Türöffnung |  | 0 | NEW | 1113Wa 0812549763 | AllplanAttributes - Codetext: Codetext; Türanschlag: -; Attributset-Objekt: OpeningElement; W_Deckenanschluss: Gleitender Deckenanschluss Fall 01; Positionsnummer_Text: S68; Ortscode_Geschoßbezeichnung: E00; Pset_OpeningElementCommon - FireExit: no; Reference: Codetext
Türöffnung | H2 Ebene 0 | 1113Tür0812549652 | m² |  | Trockenbauarbeiten | Türöffnung |  | 0 | NEW | 1113Wa 0812549763 | EI2 30 | AllplanAttributes - Codetext: Codetext; Türanschlag: -; Attributset-Objekt: OpeningElement; Rauchschutz: yes; Selbstschließend: yes; ash T_Zulage Schachttür: no; ash T_Dichtschließend: no; ash T_Feststellanlage (FSA): -; ash T_nicht abschließbar: no; W_Deckenanschluss: Gleitender Deckenanschluss Fall 01; Positionsnummer_Text: S68; Ortscode_Geschoßbezeichnung: E00; Pset_OpeningElementCommon - FireExit: no; Reference: Codetext
SMT | H2 Ebene 0 | 1113Tür0812436302 | m² |  | Zimmer- und Holzbauarbeiten | Türmakro |  | 0 | NEW | 1113Wa 0812437646 | AllplanAttributes - Material: TI-1F-UZ-D; Codetext: Codetext; Türanschlag: DIN L; Attributset-Objekt: Door; Glasanteil_berücksichtigen: 100; ash T_Zulage Schachttür: no; ash T_Dichtschließend: no; ash T_Zarge_Typ: U; ash T_Erforderl. Durchgangsbreite: 0 m; ash T_Türblatt sichtbar 2D: ja; ash T_Feststellanlage (FSA): -; ash T_nicht abschließbar: no; ash T_Tür-Nr.: Innentür 1; ash T_Blatt_Oberfläche: -; ash T_Erford. Durgangshöhe: 0 m; ash T_Blatt_Material: -; ash T_Schallschutz: -; ash T_Zarge_Material: S; ash T_Raum zugehörigkeit: BS; Positionsnummer_Text: S68; Pset_OpeningElementCommon - FireExit: no; Reference: Codetext; DoorCommon - Außenliegend: no; Feuerwiderstandsklasse: EI2 30; Rauchschutz: yes; Selbstschließend: yes
Türöffnung | H2 Ebene 0 | 1113Tür0812655401 | m² |  | Trockenbauarbeiten | Türöffnung |  | 0 | NEW | 1113Wa 0812655407 | AllplanAttributes - Codetext: Codetext; Türanschlag: DIN L; Attributset-Objekt: OpeningElement; Positionsnummer_Text: S68; Pset_OpeningElementCommon - FireExit: no; Reference: Codetext
Türöffnung | H2 Ebene 0 | 1113Tür0812655403 | m² |  | Trockenbauarbeiten | Türöffnung |  | 0 | NEW | 1113Wa 0812655407 | AllplanAttributes - Codetext: Codetext; Türanschlag: DIN R; Attributset-Objekt: OpeningElement; Positionsnummer_Text: S68; Pset_OpeningElementCommon - FireExit: no; Reference: Codetext
Türöffnung | H2 Ebene 0 | 1113Tür0812440139 | m² |  | Trockenbauarbeiten | Türöffnung |  | 0 | NEW | 1113Wa 0812440257 | AllplanAttributes - Codetext: Codetext; Türanschlag: -; Attributset-Objekt: OpeningElement; W_Deckenanschluss: Gleitender Deckenanschluss Fall 01; Positionsnummer_Text: S68; Ortscode_Geschoßbezeichnung: E00; Pset_OpeningElementCommon - FireExit: no; Reference: Codetext
Türöffnung | H2 Ebene 0 | 1113Tür0812436847 | m² |  | Trockenbauarbeiten | Türöffnung |  | 0 | NEW | 1113Wa 0812438242 | AllplanAttributes - Bezeichnung: Türöffnung; Codetext: Codetext; Türanschlag: -; Attributset-Objekt: OpeningElement; W_Deckenanschluss: Gleitender Deckenanschluss Fall 01; Positionsnummer_Text: S68; Ortscode_Geschoßbezeichnung: E00; Pset_OpeningElementCommon - FireExit: no; Reference: Codetext
Türöffnung | H2 Ebene 0 | 1113Tür0812436838 | m² |  | Trockenbauarbeiten | Türöffnung |  | 0 | NEW | 1113Wa 0812438254 | AllplanAttributes - Bezeichnung: Türöffnung; Codetext: Codetext; Türanschlag: -; Attributset-Objekt: OpeningElement; W_Deckenanschluss: Gleitender Deckenanschluss Fall 01; Positionsnummer_Text: S68; Ortscode_Geschoßbezeichnung: E00; Pset_OpeningElementCommon - FireExit: no; Reference: Codetext
Türöffnung | H2 Ebene 0 | 1113Tür0812436855 | m² |  | Trockenbauarbeiten | Türöffnung |  | 0 | NEW | 1113Wa 0812438258 | AllplanAttributes - Bezeichnung: Türöffnung; Codetext: Codetext; Türanschlag: -; Attributset-Objekt: OpeningElement; W_Deckenanschluss: Gleitender Deckenanschluss Fall 01; Positionsnummer_Text: S68; Ortscode_Geschoßbezeichnung: E00; Pset_OpeningElementCommon - FireExit: no; Reference: Codetext
Türöffnung | H2 Ebene 0 | 1113Tür0812436851 | m² |  | Trockenbauarbeiten | Türöffnung |  | 0 | NEW | 1113Wa 0812438238 | AllplanAttributes - Codetext: Codetext; Türanschlag: -; Attributset-Objekt: OpeningElement; W_Deckenanschluss: Gleitender Deckenanschluss Fall 01; Positionsnummer_Text: S68; Ortscode_Geschoßbezeichnung: E00; Pset_OpeningElementCommon - FireExit: no; Reference: Codetext
Türöffnung | H2 Ebene 0 | 1113Tür0812436859 | m² |  | Trockenbauarbeiten | Türöffnung |  | 0 | NEW | 1113Wa 0812438250 | AllplanAttributes - Bezeichnung: Türöffnung; Codetext: Codetext; Türanschlag: -; Attributset-Objekt: OpeningElement; W_Deckenanschluss: Gleitender Deckenanschluss Fall 01; Positionsnummer_Text: S68; Ortscode_Geschoßbezeichnung: E00; Pset_OpeningElementCommon - FireExit: no; Reference: Codetext
Türöffnung | H2 Ebene 0 | 1113Tür0812435681 | m² |  | Trockenbauarbeiten | Türöffnung |  | 0 | NEW | 1113Wa 0812446900 | AllplanAttributes - Bezeichnung: Türöffnung; Codetext: Codetext; Türanschlag: -; Attributset-Objekt: OpeningElement; W_Deckenanschluss: Gleitender Deckenanschluss Fall 01; Positionsnummer_Text: S68; Ortscode_Geschoßbezeichnung: E00; Pset_OpeningElementCommon - FireExit: no; Reference: Codetext
Türöffnung | H2 Ebene 0 | 1113Tür0812435685 | m² |  | Trockenbauarbeiten | Türöffnung |  | 0 | NEW | 1113Wa 0812446900 | AllplanAttributes - Bezeichnung: Türöffnung; Codetext: Codetext; Türanschlag: -; Attributset-Objekt: OpeningElement; W_Deckenanschluss: Gleitender Deckenanschluss Fall 01; Positionsnummer_Text: S68; Ortscode_Geschoßbezeichnung: E00; Pset_OpeningElementCommon - FireExit: no; Reference: Codetext
SMT | H2 Ebene 0 | 1113Tür0812440816 | m² |  | Zimmer- und Holzbauarbeiten | Türmakro |  | 0 | NEW | 1113Wa 0812443013 | AllplanAttributes - Material: TI-1F-UZ-D; Codetext: Codetext; Türanschlag: DIN R; Attributset-Objekt: Door; Glasanteil_berücksichtigen: 100; ash T_Zulage Schachttür: no; ash T_Dichtschließend: no; ash T_Zarge_Typ: U; ash T_Erforderl. Durchgangsbreite: 0 m; ash T_Türblatt sichtbar 2D: ja; ash T_Feststellanlage (FSA): -; ash T_nicht abschließbar: no; ash T_Tür-Nr.: Innentür 1; ash T_Blatt_Oberfläche: -; ash T_Erford. Durgangshöhe: 0 m; ash T_Blatt_Material: -; ash T_Schallschutz: -; ash T_Zarge_Material: S; ash T_Raum zugehörigkeit: BS; Positionsnummer_Text: S68; Pset_OpeningElementCommon - FireExit: no; Reference: Codetext; DoorCommon - Außenliegend: no; Feuerwiderstandsklasse: EI2 30; Rauchschutz: yes; Selbstschließend: yes
Türöffnung | H2 Ebene 0 | 1113Tür0812742291 | m² |  | Trockenbauarbeiten | Türöffnung |  | 0 | NEW | 1113Wa 0812742684 | EI2 30 | AllplanAttributes - Codetext: Codetext; Türanschlag: -; Attributset-Objekt: OpeningElement; Rauchschutz: yes; Selbstschließend: yes; ash T_Zulage Schachttür: no; ash T_Dichtschließend: no; ash T_Feststellanlage (FSA): -; ash T_nicht abschließbar: no; W_Deckenanschluss: Gleitender Deckenanschluss Fall 01; Positionsnummer_Text: S68; Ortscode_Geschoßbezeichnung: E00; Pset_OpeningElementCommon - FireExit: no; Reference: Codetext
Türöffnung | H2 Ebene 0 | 1113Tür0812742290 | m² |  | Trockenbauarbeiten | Türöffnung |  | 0 | NEW | 1113Wa 0812742684 | EI2 30 | AllplanAttributes - Codetext: Codetext; Türanschlag: -; Attributset-Objekt: OpeningElement; Rauchschutz: yes; Selbstschließend: yes; ash T_Zulage Schachttür: no; ash T_Dichtschließend: no; ash T_Feststellanlage (FSA): -; ash T_nicht abschließbar: no; W_Deckenanschluss: Gleitender Deckenanschluss Fall 01; Positionsnummer_Text: S68; Ortscode_Geschoßbezeichnung: E00; Pset_OpeningElementCommon - FireExit: no; Reference: Codetext
Türöffnung | H2 Ebene 0 | 1113Tür0812443594 | m² |  | Trockenbauarbeiten | Türöffnung |  | 0 | NEW | 1113Wa 0812443694 | AllplanAttributes - Codetext: Codetext; Türanschlag: DIN L; Attributset-Objekt: OpeningElement; Positionsnummer_Text: S68; Pset_OpeningElementCommon - FireExit: no; Reference: Codetext
Türöffnung | H2 Ebene 0 | 1113Tür0812443590 | m² |  | Trockenbauarbeiten | Türöffnung |  | 0 | NEW | 1113Wa 0812443694 | AllplanAttributes - Codetext: Codetext; Türanschlag: DIN R; Attributset-Objekt: OpeningElement; Positionsnummer_Text: S68; Pset_OpeningElementCommon - FireExit: no; Reference: Codetext
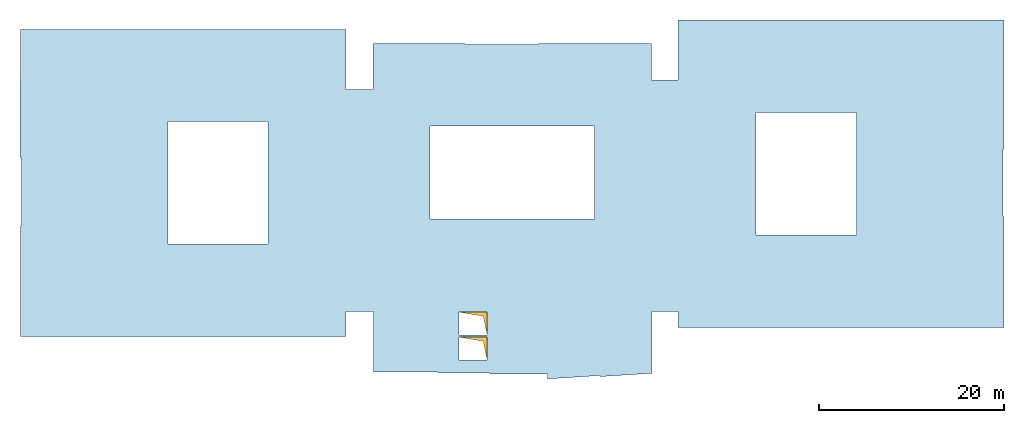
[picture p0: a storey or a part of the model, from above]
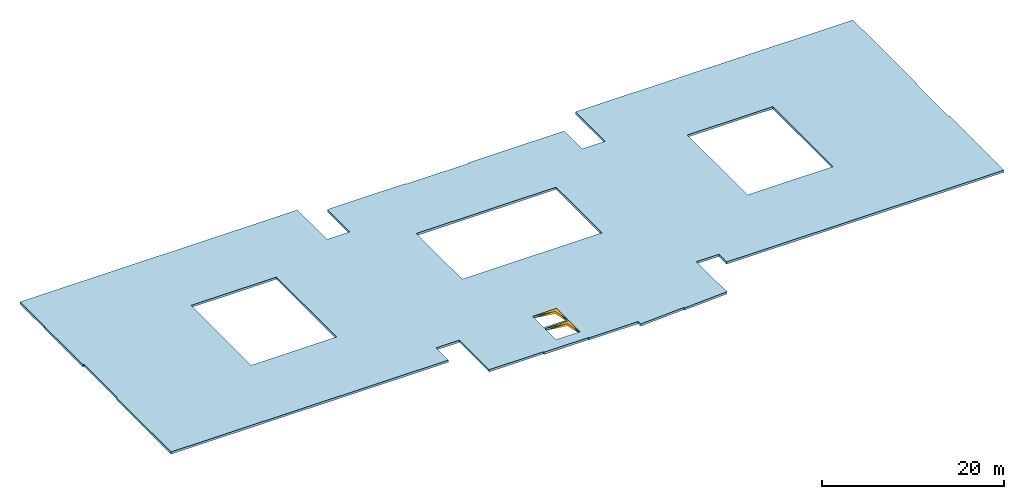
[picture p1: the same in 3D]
Properties of the parts of a building model (IFC4), part 42 of 80

# IfcOpeningElement: Opening (3497)
Name | In | Allright_Bauteil_ID | Abrechnungsart | Versatz_oben | Gewerk | Objektname | Versatz_unten | OKFF | Status | P_ID | AllplanAttributes, Feuerwiderstandsklasse | Sicherheitsklasse | g-Wert
SMT | H2 Ebene 0 | 1113Tür0812551382 | m² |  | Metallbau-, Schlosserarbeiten | Türmakro |  | 0 | NEW | 1113Wa 0812551359 | AllplanAttributes - Material: TI-1F-UZ-D; Codetext: Codetext; Türanschlag: DIN R; Attributset-Objekt: Door; Positionsnummer: 1; V6: 0 m; V7: 0 m; V8: 0 m; V9: 0; Glasanteil_berücksichtigen: 100; ash T_Unterschnitt: -; ash T_Zulage Schachttür: no; ash T_Dichtschließend: yes; ash T_Zarge_Typ: U; ash T_Erforderl. Durchgangsbreite: 0 m; ash T_Türblatt sichtbar 2D: ja; ash T_Feststellanlage (FSA): -; ash T_nicht abschließbar: no; ash T_Blatt_Oberfläche: -; ash T_Erford. Durgangshöhe: 0 m; ash T_Blatt_Material: -; ash T_Schallschutz: -; ash T_Zarge_Material: S; ash T_Raum zugehörigkeit: BS; Positionsnummer_Text: S68; Pset_OpeningElementCommon - FireExit: no; Reference: Codetext; DoorCommon - Außenliegend: no; Feuerwiderstandsklasse: -; Rauchschutz: no; Selbstschließend: no
Türöffnung | H2 Ebene 0 | 1113Tür0812436829 | m² |  | Zimmer- und Holzbauarbeiten | Türöffnung |  | 0 | NEW | 1113Wa 0812437306 | AllplanAttributes - Codetext: Codetext; Türanschlag: DIN L; Attributset-Objekt: OpeningElement; Positionsnummer_Text: S68; Pset_OpeningElementCommon - FireExit: no; Reference: Codetext
Türöffnung | H2 Ebene 0 | 1113Tür0812436834 | m² |  | Zimmer- und Holzbauarbeiten | Türöffnung |  | 0 | NEW | 1113Wa 0812437306 | EI2 30 | AllplanAttributes - Codetext: Codetext; Türanschlag: DIN L; Attributset-Objekt: OpeningElement; Rauchschutz: yes; Selbstschließend: yes; ash T_Zulage Schachttür: no; ash T_Dichtschließend: no; ash T_Feststellanlage (FSA): -; ash T_nicht abschließbar: no; Positionsnummer_Text: S68; Pset_OpeningElementCommon - FireExit: no; Reference: Codetext
Türöffnung | H2 Ebene 0 | 1113Tür0812972386 | m² |  | Zimmer- und Holzbauarbeiten | Türöffnung |  | 0 | NEW | 1113Wa 0812852060 | E 60 | AllplanAttributes - Türanschlag: -; Text1: 15a; Positionsnummer_Text: S68
Türöffnung | H2 Ebene 0 | 1113Tür0812852030 | m² |  | Zimmer- und Holzbauarbeiten | Türöffnung |  | 0 | NEW | 1113Wa 0812852060 | E 60 | AllplanAttributes - Türanschlag: -; Text1: 15a; Positionsnummer_Text: S68
Wandnische | H2 Ebene 0 | 1113Wni0814028848 | m² | 0 | Zimmer- und Holzbauarbeiten | Wandnische | 0 |  | NEW | 1113Wa 0812852060
Türöffnung | H2 Ebene 0 | 1113Tür0812435693 | m² |  | Trockenbauarbeiten | Türöffnung |  | 0 | NEW | 1113Wa 0812442525 | AllplanAttributes - Codetext: Codetext; Türanschlag: -; Attributset-Objekt: OpeningElement; W_Deckenanschluss: Gleitender Deckenanschluss Fall 01; Positionsnummer_Text: S68; Ortscode_Geschoßbezeichnung: E00; Pset_OpeningElementCommon - FireExit: no; Reference: Codetext
Fensteröffnung | H2 Ebene 0 | 1113Fen0813442851 | m² |  | Fensterarbeiten | Fensteröffnung |  | 0 |  | 1113Wa 0812442525 | AllplanAttributes - W_Deckenanschluss: Gleitender Deckenanschluss Fall 01; Positionsnummer_Text: S68
Türöffnung | H2 Ebene 0 | 1113Tür0812833390 | m² |  | Trockenbauarbeiten | Türöffnung |  | 0 | NEW | 1113Wa 0812438767 | AllplanAttributes - Codetext: Codetext; Türanschlag: -; Attributset-Objekt: OpeningElement; W_Deckenanschluss: Gleitender Deckenanschluss Fall 01; Positionsnummer_Text: S68; Ortscode_Geschoßbezeichnung: E00; Pset_OpeningElementCommon - FireExit: no; Reference: Codetext
Fensteröffnung | H2 Ebene 0 | 1113Fen0813443001 | m² | 0 | Fensterarbeiten | Fensteröffnung | 0 | 0 |  | 1113Wa 0812438767 | AllplanAttributes - W_Deckenanschluss: Gleitender Deckenanschluss Fall 01; Positionsnummer_Text: S68
Türöffnung | H2 Ebene 0 | 1113Tür0812523044 | m² |  | Zimmer- und Holzbauarbeiten | Türöffnung |  | 0 | NEW | 1113Wa 0812444104 | AllplanAttributes - Codetext: Codetext; Türanschlag: DIN R; Attributset-Objekt: OpeningElement; Positionsnummer_Text: S68; Pset_OpeningElementCommon - FireExit: no; Reference: Codetext
Türöffnung | H2 Ebene 0 | 1113Tür0813135250 | m² | 0 | Zimmer- und Holzbauarbeiten | Türöffnung | 0 | 0 | NEW | 1113Wa 0813135230 | AllplanAttributes - Türanschlag: DIN R; Positionsnummer_Text: S68
Türöffnung | H2 Ebene 0 | 1113Tür0812435729 | m² |  | Zimmer- und Holzbauarbeiten | Türöffnung |  | 0 | NEW | 1113Wa 0812447147 | AllplanAttributes - Codetext: Codetext; Türanschlag: DIN L; Attributset-Objekt: OpeningElement; Positionsnummer_Text: S68; Pset_OpeningElementCommon - FireExit: no; Reference: Codetext
Türöffnung | H2 Ebene 0 | 1113Tür0813126822 | m² | 0 | Zimmer- und Holzbauarbeiten | Türöffnung | 0 | 0 | NEW | 1113Wa 0813126806 | AllplanAttributes - Türanschlag: DIN L; Positionsnummer_Text: S68
Türöffnung | H2 Ebene 0 | 1113Tür0813126823 | m² | 0 | Zimmer- und Holzbauarbeiten | Türöffnung | 0 | 0 | NEW | 1113Wa 0813126807 | AllplanAttributes - Türanschlag: DIN L; Positionsnummer_Text: S68
Türöffnung | H2 Ebene 0 | 1113Tür0812438158 | m² |  | Zimmer- und Holzbauarbeiten | Türöffnung |  | 0 | NEW | 1113Wa 0812447441 | AllplanAttributes - Codetext: Codetext; Türanschlag: DIN R; Attributset-Objekt: OpeningElement; Positionsnummer_Text: S68; Pset_OpeningElementCommon - FireExit: no; Reference: Codetext
Türöffnung | H2 Ebene 0 | 1113Tür0813129841 | m² | 0 | Zimmer- und Holzbauarbeiten | Türöffnung | 0 | 0 | NEW | 1113Wa 0813129825 | AllplanAttributes - Türanschlag: DIN R; Positionsnummer_Text: S68
Türöffnung | H2 Ebene 0 | 1113Tür0813129842 | m² | 0 | Zimmer- und Holzbauarbeiten | Türöffnung | 0 | 0 | NEW | 1113Wa 0813129826 | AllplanAttributes - Türanschlag: DIN R; Positionsnummer_Text: S68
Türöffnung | H2 Ebene 0 | 1113Tür0812492974 | m² |  | Zimmer- und Holzbauarbeiten | Türöffnung |  | 0 | NEW | 1113Wa 0812492978 | AllplanAttributes - Codetext: Codetext; Türanschlag: DIN L; Attributset-Objekt: OpeningElement; Positionsnummer_Text: S68; Pset_OpeningElementCommon - FireExit: no; Reference: Codetext
Türöffnung | H2 Ebene 0 | 1113Tür0813133218 | m² | 0 | Zimmer- und Holzbauarbeiten | Türöffnung | 0 | 0 | NEW | 1113Wa 0813132861 | AllplanAttributes - Türanschlag: DIN L; Positionsnummer_Text: S68
Türöffnung | H2 Ebene 0 | 1113Tür0813133219 | m² | 0 | Zimmer- und Holzbauarbeiten | Türöffnung | 0 | 0 | NEW | 1113Wa 0813132862 | AllplanAttributes - Türanschlag: DIN L; Positionsnummer_Text: S68
Türöffnung | H2 Ebene 0 | 1113Tür0812535682 | m² | 0 | Trockenbauarbeiten | Türöffnung | 0 | 0 | NEW | 1113Wa 0812447085 | AllplanAttributes - Codetext: Codetext; Türanschlag: -; Attributset-Objekt: OpeningElement; W_Deckenanschluss: Gleitender Deckenanschluss Fall 01; Positionsnummer_Text: S68; Ortscode_Geschoßbezeichnung: E00; Pset_OpeningElementCommon - FireExit: no; Reference: Codetext
Türöffnung | H2 Ebene 0 | 1113Tür0812435696 | m² |  | Zimmer- und Holzbauarbeiten | Türöffnung |  | 0 | NEW | 1113Wa 0812447102 | AllplanAttributes - Codetext: Codetext; Türanschlag: DIN L; Attributset-Objekt: OpeningElement; Positionsnummer_Text: S68; Pset_OpeningElementCommon - FireExit: no; Reference: Codetext
Türöffnung | H2 Ebene 0 | 1113Tür0813140715 | m² | 0 | Zimmer- und Holzbauarbeiten | Türöffnung | 0 | 0 | NEW | 1113Wa 0813140702 | AllplanAttributes - Türanschlag: -; Positionsnummer_Text: S68
Türöffnung | H2 Ebene 0 | 1113Tür0813517671 | m² |  | Zimmer- und Holzbauarbeiten | Türöffnung |  | 0 | NEW | 1113Wa 0813517682 | AllplanAttributes - Codetext: Codetext; Türanschlag: DIN L; Attributset-Objekt: OpeningElement; Positionsnummer_Text: S68; Pset_OpeningElementCommon - FireExit: no; Reference: Codetext
Türöffnung | H2 Ebene 0 | 1113Tür0813517678 | m² | 0 | Zimmer- und Holzbauarbeiten | Türöffnung | 0 | 0 | NEW | 1113Wa 0813517686 | AllplanAttributes - Türanschlag: DIN L; Positionsnummer_Text: S68
Türöffnung | H2 Ebene 0 | 1113Tür0813517679 | m² | 0 | Zimmer- und Holzbauarbeiten | Türöffnung | 0 | 0 | NEW | 1113Wa 0813517681 | AllplanAttributes - Türanschlag: DIN L; Positionsnummer_Text: S68
Türöffnung | H2 Ebene 0 | 1113Tür0812443194 | m² |  | Zimmer- und Holzbauarbeiten | Türöffnung |  | 0 | NEW | 1113Wa 0812444061 | AllplanAttributes - Codetext: Codetext; Türanschlag: DIN R; Attributset-Objekt: OpeningElement; Positionsnummer_Text: S68; Pset_OpeningElementCommon - FireExit: no; Reference: Codetext
Türöffnung | H2 Ebene 0 | 1113Tür0813118559 | m² | 0 | Zimmer- und Holzbauarbeiten | Türöffnung | 0 | 0 | NEW | 1113Wa 0813118208 | AllplanAttributes - Türanschlag: DIN R; Positionsnummer_Text: S68
Türöffnung | H2 Ebene 0 | 1113Tür0813121030 | m² | 0 | Zimmer- und Holzbauarbeiten | Türöffnung | 0 | 0 | NEW | 1113Wa 0813120985 | AllplanAttributes - Türanschlag: DIN R; Positionsnummer_Text: S68
Türöffnung | H2 Ebene 0 | 1113Tür0812435745 | m² | 0 | Trockenbauarbeiten | Türöffnung | 0 | 0 | NEW | 1113Wa 0812437922 | AllplanAttributes - Codetext: Codetext; Türanschlag: -; Attributset-Objekt: OpeningElement; ash T_Schallschutz: 37 dB; W_Deckenanschluss: Gleitender Deckenanschluss Fall 01; Positionsnummer_Text: S68; Ortscode_Geschoßbezeichnung: E00; Pset_OpeningElementCommon - FireExit: no; Reference: Codetext
Türöffnung | H2 Ebene 0 | 1113Tür0812436871 | m² |  | Trockenbauarbeiten | Türöffnung |  | 0 | NEW | 1113Wa 0812439312 | AllplanAttributes - Bezeichnung: Türöffnung; Codetext: Codetext; Türanschlag: -; Attributset-Objekt: OpeningElement; W_Deckenanschluss: Gleitender Deckenanschluss Fall 01; Positionsnummer_Text: S68; Ortscode_Geschoßbezeichnung: E00; Pset_OpeningElementCommon - FireExit: no; Reference: Codetext
Türöffnung | H2 Ebene 0 | 1113Tür0812436883 | m² |  | Trockenbauarbeiten | Türöffnung |  | 0 | NEW | 1113Wa 0812439344 | AllplanAttributes - Bezeichnung: Türöffnung; Codetext: Codetext; Türanschlag: -; Attributset-Objekt: OpeningElement; W_Deckenanschluss: Gleitender Deckenanschluss Fall 01; Positionsnummer_Text: S68; Ortscode_Geschoßbezeichnung: E00; Pset_OpeningElementCommon - FireExit: no; Reference: Codetext
Türöffnung | H2 Ebene 0 | 1113Tür0812436879 | m² |  | Trockenbauarbeiten | Türöffnung |  | 0 | NEW | 1113Wa 0812439340 | AllplanAttributes - Codetext: Codetext; Türanschlag: -; Attributset-Objekt: OpeningElement; W_Deckenanschluss: Gleitender Deckenanschluss Fall 01; Positionsnummer_Text: S68; Ortscode_Geschoßbezeichnung: E00; Pset_OpeningElementCommon - FireExit: no; Reference: Codetext
Türöffnung | H2 Ebene 0 | 1113Tür0812436875 | m² |  | Trockenbauarbeiten | Türöffnung |  | 0 | NEW | 1113Wa 0812439316 | AllplanAttributes - Bezeichnung: Türöffnung; Codetext: Codetext; Türanschlag: -; Attributset-Objekt: OpeningElement; W_Deckenanschluss: Gleitender Deckenanschluss Fall 01; Positionsnummer_Text: S68; Ortscode_Geschoßbezeichnung: E00; Pset_OpeningElementCommon - FireExit: no; Reference: Codetext
Türöffnung | H2 Ebene 0 | 1113Tür0814015585 | m² | 0 | Zimmer- und Holzbauarbeiten | Türöffnung | 0 | 0 | NEW | 1113Wa 0814015503 | AllplanAttributes - Codetext: Codetext; Türanschlag: DIN L; Attributset-Objekt: OpeningElement; Positionsnummer_Text: S68; Pset_OpeningElementCommon - FireExit: no; Reference: Codetext
Türöffnung | H2 Ebene 0 | 1113Tür0814015584 | m² | 0 | Zimmer- und Holzbauarbeiten | Türöffnung | 0 | 0 | NEW | 1113Wa 0814015504 | AllplanAttributes - Türanschlag: DIN L; Positionsnummer_Text: S68
Türöffnung | H2 Ebene 0 | 1113Tür0814015583 | m² | 0 | Zimmer- und Holzbauarbeiten | Türöffnung | 0 |  | NEW | 1113Wa 0814015505 | AllplanAttributes - Türanschlag: DIN L
Türöffnung | H2 Ebene 0 | 1113Tür0812436824 | m² |  | Trockenbauarbeiten | Türöffnung |  | 0 | NEW | 1113Wa 0812437379 | AllplanAttributes - Codetext: Codetext; Türanschlag: -; Attributset-Objekt: OpeningElement; W_Deckenanschluss: Gleitender Deckenanschluss Fall 01; Positionsnummer_Text: S68; Ortscode_Geschoßbezeichnung: E00; Pset_OpeningElementCommon - FireExit: no; Reference: Codetext
Türöffnung | H2 Ebene 0 | 1113Tür0813516857 | m² |  | Zimmer- und Holzbauarbeiten | Türöffnung |  | 0 | NEW | 1113Wa 0813516874 | AllplanAttributes - Codetext: Codetext; Türanschlag: DIN R; Attributset-Objekt: OpeningElement; Positionsnummer_Text: S68; Pset_OpeningElementCommon - FireExit: no; Reference: Codetext
Türöffnung | H2 Ebene 0 | 1113Tür0813516864 | m² | 0 | Zimmer- und Holzbauarbeiten | Türöffnung | 0 | 0 | NEW | 1113Wa 0813516873 | AllplanAttributes - Türanschlag: DIN R; Positionsnummer_Text: S68
Türöffnung | H2 Ebene 0 | 1113Tür0813516863 | m² | 0 | Zimmer- und Holzbauarbeiten | Türöffnung | 0 | 0 | NEW | 1113Wa 0813516876 | AllplanAttributes - Türanschlag: DIN R; Positionsnummer_Text: S68
Türöffnung | H2 Ebene 0 | 1113Tür0814115561 | m² |  | Zimmer- und Holzbauarbeiten | Türöffnung |  | 0 | NEW | 1113Wa 0814115959 | AllplanAttributes - Codetext: Codetext; Türanschlag: -; Attributset-Objekt: OpeningElement; Positionsnummer_Text: S68; Pset_OpeningElementCommon - FireExit: no; Reference: Codetext
Türöffnung | H2 Ebene 0 | 1113Tür0814115560 | m² | 0 | Zimmer- und Holzbauarbeiten | Türöffnung | 0 | 0 | NEW | 1113Wa 0814115963 | AllplanAttributes - Türanschlag: -; Positionsnummer_Text: S68
Türöffnung | H2 Ebene 0 | 1113Tür0814121344 | m² |  | Zimmer- und Holzbauarbeiten | Türöffnung |  | 0 | NEW | 1113Wa 0814121386 | AllplanAttributes - Codetext: Codetext; Türanschlag: -; Attributset-Objekt: OpeningElement; Positionsnummer_Text: S68; Pset_OpeningElementCommon - FireExit: no; Reference: Codetext
Türöffnung | H2 Ebene 0 | 1113Tür0814121365 | m² |  | Zimmer- und Holzbauarbeiten | Türöffnung |  | 0 | NEW | 1113Wa 0814121386 | AllplanAttributes - Codetext: Codetext; Türanschlag: -; Attributset-Objekt: OpeningElement; Positionsnummer_Text: S68; Pset_OpeningElementCommon - FireExit: no; Reference: Codetext
Türöffnung | H2 Ebene 0 | 1113Tür0814121364 | m² | 0 | Zimmer- und Holzbauarbeiten | Türöffnung | 0 | 0 | NEW | 1113Wa 0814121391 | AllplanAttributes - Türanschlag: -; Positionsnummer_Text: S68
Türöffnung | H2 Ebene 0 | 1113Tür0814121343 | m² | 0 | Zimmer- und Holzbauarbeiten | Türöffnung | 0 | 0 | NEW | 1113Wa 0814121391 | AllplanAttributes - Türanschlag: -; Positionsnummer_Text: S68
Türöffnung | H2 Ebene 0 | 1113Tür0812441388 | m² |  | Trockenbauarbeiten | Türöffnung |  | 0 | NEW | 1113Wa 0812441634 | AllplanAttributes - Bezeichnung: Türöffnung; Codetext: Codetext; Türanschlag: -; Attributset-Objekt: OpeningElement; Positionsnummer_Text: S68; Ortscode_Geschoßbezeichnung: E00; Pset_OpeningElementCommon - FireExit: no; Reference: Codetext
Türöffnung | H2 Ebene 0 | 1113Tür0812441498 | m² |  | Trockenbauarbeiten | Türöffnung |  | 0 | NEW | 1113Wa 0812441697 | AllplanAttributes - Bezeichnung: Türöffnung; Codetext: Codetext; Türanschlag: -; Attributset-Objekt: OpeningElement; Positionsnummer_Text: S68; Ortscode_Geschoßbezeichnung: E00; Pset_OpeningElementCommon - FireExit: no; Reference: Codetext
Türöffnung | H2 Ebene 0 | 1113Tür0812446114 | m² |  | Zimmer- und Holzbauarbeiten | Türöffnung |  | 0 | NEW | 1113Wa 0812446773 | AllplanAttributes - Codetext: Codetext; Türanschlag: -; Attributset-Objekt: OpeningElement; Positionsnummer_Text: S68; Pset_OpeningElementCommon - FireExit: no; Reference: Codetext
Türöffnung | H2 Ebene 0 | 1113Tür0814126110 | m² | 0 | Zimmer- und Holzbauarbeiten | Türöffnung | 0 |  | NEW | 1113Wa 0814126098 | AllplanAttributes - Türanschlag: -
Türöffnung | H2 Ebene 0 | 1113Tür0812445985 | m² |  | Trockenbauarbeiten | Türöffnung |  | 0 | NEW | 1113Wa 0812446171 | AllplanAttributes - Bezeichnung: Türöffnung; Codetext: Codetext; Türanschlag: -; Attributset-Objekt: OpeningElement; W_Deckenanschluss: Gleitender Deckenanschluss Fall 01; Positionsnummer_Text: S68; Ortscode_Geschoßbezeichnung: E00; Pset_OpeningElementCommon - FireExit: no; Reference: Codetext
Türöffnung | H2 Ebene 0 | 1113Tür0812445989 | m² |  | Trockenbauarbeiten | Türöffnung |  | 0 | NEW | 1113Wa 0812446187 | AllplanAttributes - Bezeichnung: Türöffnung; Codetext: Codetext; Türanschlag: -; Attributset-Objekt: OpeningElement; W_Deckenanschluss: Gleitender Deckenanschluss Fall 01; Positionsnummer_Text: S68; Ortscode_Geschoßbezeichnung: E00; Pset_OpeningElementCommon - FireExit: no; Reference: Codetext
Türöffnung | H2 Ebene 0 | 1113Tür0814125150 | m² |  | Zimmer- und Holzbauarbeiten | Türöffnung |  | 0 | NEW | 1113Wa 0814125182 | AllplanAttributes - Codetext: Codetext; Türanschlag: -; Attributset-Objekt: OpeningElement; Positionsnummer_Text: S68; Pset_OpeningElementCommon - FireExit: no; Reference: Codetext
Türöffnung | H2 Ebene 0 | 1113Tür0814125176 | m² |  | Zimmer- und Holzbauarbeiten | Türöffnung |  | 0 | NEW | 1113Wa 0814125182 | AllplanAttributes - Codetext: Codetext; Türanschlag: -; Attributset-Objekt: OpeningElement; Positionsnummer_Text: S68; Pset_OpeningElementCommon - FireExit: no; Reference: Codetext
Türöffnung | H2 Ebene 0 | 1113Tür0814125149 | m² | 0 | Zimmer- und Holzbauarbeiten | Türöffnung | 0 | 0 | NEW | 1113Wa 0814125184 | AllplanAttributes - Türanschlag: -; Positionsnummer_Text: S68
Türöffnung | H2 Ebene 0 | 1113Tür0814125175 | m² | 0 | Zimmer- und Holzbauarbeiten | Türöffnung | 0 | 0 | NEW | 1113Wa 0814125184 | AllplanAttributes - Türanschlag: -; Positionsnummer_Text: S68
Türöffnung | H2 Ebene 0 | 1113Tür0812445981 | m² |  | Trockenbauarbeiten | Türöffnung |  | 0 | NEW | 1113Wa 0812446175 | AllplanAttributes - Codetext: Codetext; Türanschlag: -; Attributset-Objekt: OpeningElement; W_Deckenanschluss: Gleitender Deckenanschluss Fall 01; Positionsnummer_Text: S68; Ortscode_Geschoßbezeichnung: E00; Pset_OpeningElementCommon - FireExit: no; Reference: Codetext
Türöffnung | H2 Ebene 0 | 1113Tür0812445977 | m² |  | Trockenbauarbeiten | Türöffnung |  | 0 | NEW | 1113Wa 0812446183 | AllplanAttributes - Bezeichnung: Türöffnung; Codetext: Codetext; Türanschlag: -; Attributset-Objekt: OpeningElement; W_Deckenanschluss: Gleitender Deckenanschluss Fall 01; Positionsnummer_Text: S68; Ortscode_Geschoßbezeichnung: E00; Pset_OpeningElementCommon - FireExit: no; Reference: Codetext
Türöffnung | H2 Ebene 0 | 1113Tür0814128469 | m² |  | Zimmer- und Holzbauarbeiten | Türöffnung |  | 0 | NEW | 1113Wa 0814128496 | AllplanAttributes - Codetext: Codetext; Türanschlag: -; Attributset-Objekt: OpeningElement; Positionsnummer_Text: S68; Pset_OpeningElementCommon - FireExit: no; Reference: Codetext
Türöffnung | H2 Ebene 0 | 1113Tür0814128483 | m² |  | Zimmer- und Holzbauarbeiten | Türöffnung |  | 0 | NEW | 1113Wa 0814128496 | - | AllplanAttributes - Codetext: Codetext; Türanschlag: -; Attributset-Objekt: OpeningElement; Rauchschutz: no; Selbstschließend: no; ash T_Unterschnitt: -; ash T_Zulage Schachttür: no; ash T_Dichtschließend: yes; ash T_Feststellanlage (FSA): -; ash T_nicht abschließbar: no; Positionsnummer_Text: S68; Pset_OpeningElementCommon - FireExit: no; Reference: Codetext
Türöffnung | H2 Ebene 0 | 1113Tür0814128482 | m² | 0 | Zimmer- und Holzbauarbeiten | Türöffnung | 0 | 0 | NEW | 1113Wa 0814128494 | AllplanAttributes - Türanschlag: -; Positionsnummer_Text: S68
Türöffnung | H2 Ebene 0 | 1113Tür0814128475 | m² | 0 | Zimmer- und Holzbauarbeiten | Türöffnung | 0 | 0 | NEW | 1113Wa 0814128494 | AllplanAttributes - Türanschlag: -; Positionsnummer_Text: S68
Türöffnung | H2 Ebene 0 | 1113Tür0812445973 | m² |  | Trockenbauarbeiten | Türöffnung |  | 0 | NEW | 1113Wa 0812446179 | AllplanAttributes - Bezeichnung: Türöffnung; Codetext: Codetext; Türanschlag: -; Attributset-Objekt: OpeningElement; W_Deckenanschluss: Gleitender Deckenanschluss Fall 01; Positionsnummer_Text: S68; Ortscode_Geschoßbezeichnung: E00; Pset_OpeningElementCommon - FireExit: no; Reference: Codetext
Türöffnung | H2 Ebene 0 | 1113Tür0812445969 | m² |  | Trockenbauarbeiten | Türöffnung |  | 0 | NEW | 1113Wa 0812446167 | AllplanAttributes - Bezeichnung: Türöffnung; Codetext: Codetext; Türanschlag: -; Attributset-Objekt: OpeningElement; W_Deckenanschluss: Gleitender Deckenanschluss Fall 01; Positionsnummer_Text: S68; Ortscode_Geschoßbezeichnung: E00; Pset_OpeningElementCommon - FireExit: no; Reference: Codetext
Türöffnung | H2 Ebene 0 | 1113Tür0812446732 | m² |  | Trockenbauarbeiten | Türöffnung |  | 0 | NEW | 1113Wa 0812446743 | AllplanAttributes - Bezeichnung: Türöffnung; Codetext: Codetext; Türanschlag: -; Attributset-Objekt: OpeningElement; W_Deckenanschluss: Gleitender Deckenanschluss Fall 01; Positionsnummer_Text: S68; Ortscode_Geschoßbezeichnung: E00; Pset_OpeningElementCommon - FireExit: no; Reference: Codetext
Türöffnung | H2 Ebene 0 | 1113Tür0814133505 | m² |  | Zimmer- und Holzbauarbeiten | Türöffnung |  | 0 | NEW | 1113Wa 0814133525 | - | AllplanAttributes - Codetext: Codetext; Türanschlag: -; Attributset-Objekt: OpeningElement; Rauchschutz: no; Selbstschließend: no; ash T_Unterschnitt: -; ash T_Zulage Schachttür: no; ash T_Dichtschließend: yes; ash T_Feststellanlage (FSA): -; ash T_nicht abschließbar: no; Positionsnummer_Text: S68; Pset_OpeningElementCommon - FireExit: no; Reference: Codetext
Türöffnung | H2 Ebene 0 | 1113Tür0814133517 | m² |  | Zimmer- und Holzbauarbeiten | Türöffnung |  | 0 | NEW | 1113Wa 0814133525 | - | AllplanAttributes - Codetext: Codetext; Türanschlag: -; Attributset-Objekt: OpeningElement; Rauchschutz: no; Selbstschließend: no; ash T_Unterschnitt: -; ash T_Zulage Schachttür: no; ash T_Dichtschließend: yes; ash T_Feststellanlage (FSA): -; ash T_nicht abschließbar: no; Positionsnummer_Text: S68; Pset_OpeningElementCommon - FireExit: no; Reference: Codetext
Türöffnung | H2 Ebene 0 | 1113Tür0814133490 | m² | 0 | Zimmer- und Holzbauarbeiten | Türöffnung | 0 | 0 | NEW | 1113Wa 0814133523 | AllplanAttributes - Türanschlag: -; Positionsnummer_Text: S68
Türöffnung | H2 Ebene 0 | 1113Tür0814133492 | m² | 0 | Zimmer- und Holzbauarbeiten | Türöffnung | 0 | 0 | NEW | 1113Wa 0814133523 | AllplanAttributes - Türanschlag: -; Positionsnummer_Text: S68
Türöffnung | H2 Ebene 0 | 1113Tür0814141536 | m² |  | Zimmer- und Holzbauarbeiten | Türöffnung |  | 0 | NEW | 1113Wa 0814141545 | - | AllplanAttributes - Codetext: Codetext; Türanschlag: -; Attributset-Objekt: OpeningElement; Rauchschutz: no; Selbstschließend: no; ash T_Unterschnitt: -; ash T_Zulage Schachttür: no; ash T_Dichtschließend: yes; ash T_Feststellanlage (FSA): -; ash T_nicht abschließbar: no; Positionsnummer_Text: S68; Pset_OpeningElementCommon - FireExit: no; Reference: Codetext
Türöffnung | H2 Ebene 0 | 1113Tür0814141542 | m² | 0 | Zimmer- und Holzbauarbeiten | Türöffnung | 0 | 0 | NEW | 1113Wa 0814141543 | AllplanAttributes - Türanschlag: -; Positionsnummer_Text: S68
Türöffnung | H2 Ebene 0 | 1113Tür0814142091 | m² |  | Zimmer- und Holzbauarbeiten | Türöffnung |  | 0 | NEW | 1113Wa 0814142127 | - | AllplanAttributes - Codetext: Codetext; Türanschlag: -; Attributset-Objekt: OpeningElement; Rauchschutz: no; Selbstschließend: no; ash T_Unterschnitt: -; ash T_Zulage Schachttür: no; ash T_Dichtschließend: yes; ash T_Feststellanlage (FSA): -; ash T_nicht abschließbar: no; Positionsnummer_Text: S68; Pset_OpeningElementCommon - FireExit: no; Reference: Codetext
Türöffnung | H2 Ebene 0 | 1113Tür0814142075 | m² |  | Zimmer- und Holzbauarbeiten | Türöffnung |  | 0 | NEW | 1113Wa 0814142127 | - | AllplanAttributes - Codetext: Codetext; Türanschlag: -; Attributset-Objekt: OpeningElement; Rauchschutz: no; Selbstschließend: no; ash T_Unterschnitt: -; ash T_Zulage Schachttür: no; ash T_Dichtschließend: yes; ash T_Feststellanlage (FSA): -; ash T_nicht abschließbar: no; Positionsnummer_Text: S68; Pset_OpeningElementCommon - FireExit: no; Reference: Codetext
Türöffnung | H2 Ebene 0 | 1113Tür0814142102 | m² | 0 | Zimmer- und Holzbauarbeiten | Türöffnung | 0 | 0 | NEW | 1113Wa 0814142124 | AllplanAttributes - Türanschlag: -; Positionsnummer_Text: S68
Türöffnung | H2 Ebene 0 | 1113Tür0814142105 | m² | 0 | Zimmer- und Holzbauarbeiten | Türöffnung | 0 | 0 | NEW | 1113Wa 0814142124 | AllplanAttributes - Türanschlag: -; Positionsnummer_Text: S68
Türöffnung | H2 Ebene 0 | 1113Tür0814143152 | m² |  | Zimmer- und Holzbauarbeiten | Türöffnung |  | 0 | NEW | 1113Wa 0814143160 | - | AllplanAttributes - Codetext: Codetext; Türanschlag: -; Attributset-Objekt: OpeningElement; Rauchschutz: no; Selbstschließend: no; ash T_Unterschnitt: -; ash T_Zulage Schachttür: no; ash T_Dichtschließend: yes; ash T_Feststellanlage (FSA): -; ash T_nicht abschließbar: no; Positionsnummer_Text: S68; Pset_OpeningElementCommon - FireExit: no; Reference: Codetext
Türöffnung | H2 Ebene 0 | 1113Tür0814143149 | m² |  | Zimmer- und Holzbauarbeiten | Türöffnung |  | 0 | NEW | 1113Wa 0814143160 | - | AllplanAttributes - Codetext: Codetext; Türanschlag: -; Attributset-Objekt: OpeningElement; Rauchschutz: no; Selbstschließend: no; ash T_Unterschnitt: -; ash T_Zulage Schachttür: no; ash T_Dichtschließend: yes; ash T_Feststellanlage (FSA): -; ash T_nicht abschließbar: no; Positionsnummer_Text: S68; Pset_OpeningElementCommon - FireExit: no; Reference: Codetext
Türöffnung | H2 Ebene 0 | 1113Tür0814143156 | m² | 0 | Zimmer- und Holzbauarbeiten | Türöffnung | 0 | 0 | NEW | 1113Wa 0814143158 | AllplanAttributes - Türanschlag: -; Positionsnummer_Text: S68
Türöffnung | H2 Ebene 0 | 1113Tür0814143157 | m² | 0 | Zimmer- und Holzbauarbeiten | Türöffnung | 0 | 0 | NEW | 1113Wa 0814143158 | AllplanAttributes - Türanschlag: -; Positionsnummer_Text: S68
Türöffnung | H2 Ebene 0 | 1113Tür0812439044 | m² |  | Zimmer- und Holzbauarbeiten | Türöffnung |  | 0 | NEW | 1113Wa 0812440280 | - | AllplanAttributes - Codetext: Codetext; Türanschlag: -; Attributset-Objekt: OpeningElement; Rauchschutz: no; Selbstschließend: no; ash T_Unterschnitt: -; ash T_Zulage Schachttür: no; ash T_Dichtschließend: yes; ash T_Feststellanlage (FSA): -; ash T_nicht abschließbar: no; Positionsnummer_Text: S68; Pset_OpeningElementCommon - FireExit: no; Reference: Codetext
Türöffnung | H2 Ebene 0 | 1113Tür0813143884 | m² | 0 | Zimmer- und Holzbauarbeiten | Türöffnung | 0 | 0 | NEW | 1113Wa 0813143716 | AllplanAttributes - Türanschlag: -; Positionsnummer_Text: S68
Türöffnung | H2 Ebene 0 | 1113Tür0813518666 | m² |  | Zimmer- und Holzbauarbeiten | Türöffnung |  | 0 | NEW | 1113Wa 0813518673 | AllplanAttributes - Codetext: Codetext; Türanschlag: DIN R; Attributset-Objekt: OpeningElement; Positionsnummer_Text: S68; Pset_OpeningElementCommon - FireExit: no; Reference: Codetext
Türöffnung | H2 Ebene 0 | 1113Tür0813518659 | m² | 0 | Zimmer- und Holzbauarbeiten | Türöffnung | 0 | 0 | NEW | 1113Wa 0813518672 | AllplanAttributes - Türanschlag: DIN R; Positionsnummer_Text: S68
Türöffnung | H2 Ebene 0 | 1113Tür0813518656 | m² | 0 | Zimmer- und Holzbauarbeiten | Türöffnung | 0 | 0 | NEW | 1113Wa 0813518675 | AllplanAttributes - Türanschlag: DIN R; Positionsnummer_Text: S68
Türöffnung | H2 Ebene 0 | 1113Tür0814045825 | m² |  | Trockenbauarbeiten | Türöffnung |  | 0 | NEW | 1113Wa 0812444047 | AllplanAttributes - Bezeichnung: Türöffnung; Codetext: Codetext; Türanschlag: -; Attributset-Objekt: OpeningElement; W_Deckenanschluss: Gleitender Deckenanschluss Fall 01; Positionsnummer_Text: S68; Ortscode_Geschoßbezeichnung: E00; Pset_OpeningElementCommon - FireExit: no; Reference: Codetext
Türöffnung | H2 Ebene 0 | 1113Tür0812435798 | m² | 0 | Trockenbauarbeiten | Türöffnung | 0 | 0 | NEW | 1113Wa 0812437339 | AllplanAttributes - Codetext: Codetext; Türanschlag: -; Attributset-Objekt: OpeningElement; W_Deckenanschluss: Gleitender Deckenanschluss Fall 01; Positionsnummer_Text: S68; Ortscode_Geschoßbezeichnung: E00; Pset_OpeningElementCommon - FireExit: no; Reference: Codetext
Türöffnung | H2 Ebene 0 | 1113Tür0812435741 | m² | 0 | Trockenbauarbeiten | Türöffnung | 0 | 0 | NEW | 1113Wa 0812446956 | AllplanAttributes - Codetext: Codetext; Türanschlag: -; Attributset-Objekt: OpeningElement; W_Deckenanschluss: Gleitender Deckenanschluss Fall 01; Positionsnummer_Text: S68; Ortscode_Geschoßbezeichnung: E00; Pset_OpeningElementCommon - FireExit: no; Reference: Codetext
Türöffnung | H2 Ebene 0 | 1113Tür0814158374 | m² | 0 | Zimmer- und Holzbauarbeiten | Türöffnung | 0 | 0 | NEW | 1113Wa 0814158424 | AllplanAttributes - Codetext: Codetext; Türanschlag: DIN R; Attributset-Objekt: OpeningElement; Positionsnummer_Text: S68; Pset_OpeningElementCommon - FireExit: no; Reference: Codetext
Türöffnung | H2 Ebene 0 | 1113Tür0814158380 | m² | 0 | Zimmer- und Holzbauarbeiten | Türöffnung | 0 | 0 | NEW | 1113Wa 0814158424 | AllplanAttributes - Codetext: Codetext; Türanschlag: DIN L; Attributset-Objekt: OpeningElement; Positionsnummer_Text: S68; Pset_OpeningElementCommon - FireExit: no; Reference: Codetext
Türöffnung | H2 Ebene 0 | 1113Tür0814158373 | m² | 0 | Zimmer- und Holzbauarbeiten | Türöffnung | 0 | 0 | NEW | 1113Wa 0814158421 | AllplanAttributes - Türanschlag: DIN R; Positionsnummer_Text: S68
Türöffnung | H2 Ebene 0 | 1113Tür0814158379 | m² | 0 | Zimmer- und Holzbauarbeiten | Türöffnung | 0 | 0 | NEW | 1113Wa 0814158421 | AllplanAttributes - Türanschlag: DIN L; Positionsnummer_Text: S68
Türöffnung | H2 Ebene 0 | 1113Tür0814158375 | m² | 0 | Zimmer- und Holzbauarbeiten | Türöffnung | 0 |  | NEW | 1113Wa 0814158423 | AllplanAttributes - Türanschlag: DIN L
Türöffnung | H2 Ebene 0 | 1113Tür0814158369 | m² | 0 | Zimmer- und Holzbauarbeiten | Türöffnung | 0 | 0 | NEW | 1113Wa 0814158423 | AllplanAttributes - Türanschlag: DIN R; Positionsnummer_Text: S68
Türöffnung | H2 Ebene 0 | 1113Tür0814161146 | m² | 0 | Trockenbauarbeiten | Türöffnung | 0 | 0 | NEW | 1113Wa 0814161107 | AllplanAttributes - Codetext: Codetext; Türanschlag: -; Attributset-Objekt: OpeningElement; W_Deckenanschluss: Gleitender Deckenanschluss Fall 01; Positionsnummer_Text: S68; Pset_OpeningElementCommon - FireExit: no; Reference: Codetext
Türöffnung | H2 Ebene 0 | 1113Tür0812436863 | m² |  | Trockenbauarbeiten | Türöffnung |  | 0 | NEW | 1113Wa 0812439336 | AllplanAttributes - Bezeichnung: Türöffnung; Codetext: Codetext; Türanschlag: -; Attributset-Objekt: OpeningElement; W_Deckenanschluss: Gleitender Deckenanschluss Fall 01; Positionsnummer_Text: S68; Ortscode_Geschoßbezeichnung: E00; Pset_OpeningElementCommon - FireExit: no; Reference: Codetext
Türöffnung | H2 Ebene 0 | 1113Tür0812436867 | m² |  | Trockenbauarbeiten | Türöffnung |  | 0 | NEW | 1113Wa 0812439332 | AllplanAttributes - Bezeichnung: Türöffnung; Codetext: Codetext; Türanschlag: -; Attributset-Objekt: OpeningElement; W_Deckenanschluss: Gleitender Deckenanschluss Fall 01; Positionsnummer_Text: S68; Ortscode_Geschoßbezeichnung: E00; Pset_OpeningElementCommon - FireExit: no; Reference: Codetext
Türöffnung | H2 Ebene 0 | 1113Tür0812436192 | m² |  | Zimmer- und Holzbauarbeiten | Türöffnung |  | 0 | NEW | 1113Wa 0812437627 | AllplanAttributes - Codetext: Codetext; Türanschlag: DIN R; Attributset-Objekt: OpeningElement; Positionsnummer_Text: S68; ash_W_Trockenbau_Qualitäten: 8; Pset_OpeningElementCommon - FireExit: no; Reference: Codetext
Türöffnung | H2 Ebene 0 | 1113Tür0812436081 | m² |  | Zimmer- und Holzbauarbeiten | Türöffnung |  | 0 | NEW | 1113Wa 0812437627 | AllplanAttributes - Codetext: Codetext; Türanschlag: DIN L; Attributset-Objekt: OpeningElement; Positionsnummer_Text: S68; ash_W_Trockenbau_Qualitäten: 8; Pset_OpeningElementCommon - FireExit: no; Reference: Codetext
Türöffnung | H2 Ebene 0 | 1113Tür0813120213 | m² | 0 | Zimmer- und Holzbauarbeiten | Türöffnung | 0 | 0 | NEW | 1113Wa 0813120192 | AllplanAttributes - Türanschlag: DIN R; Positionsnummer_Text: S68
Türöffnung | H2 Ebene 0 | 1113Tür0813120333 | m² | 0 | Zimmer- und Holzbauarbeiten | Türöffnung | 0 | 0 | NEW | 1113Wa 0813120192 | AllplanAttributes - Türanschlag: DIN L; Positionsnummer_Text: S68
Türöffnung | H2 Ebene 0 | 1113Tür0812655394 | m² |  | Trockenbauarbeiten | Türöffnung |  | 0 | NEW | 1113Wa 0812655406 | AllplanAttributes - Codetext: Codetext; Türanschlag: DIN L; Attributset-Objekt: OpeningElement; Positionsnummer_Text: S68; ash_W_Trockenbau_Qualitäten: 8; Pset_OpeningElementCommon - FireExit: no; Reference: Codetext
Türöffnung | H2 Ebene 0 | 1113Tür0813433187 | m² | 0 | Trockenbauarbeiten | Türöffnung | 0 | 0 | NEW | 1113Wa 0813433176 | AllplanAttributes - Türanschlag: DIN L; Positionsnummer_Text: S68
SMT | H2 Ebene 0 | 1113Tür0812442214 | m² |  | Zimmer- und Holzbauarbeiten | Türmakro |  | 0 | NEW | 1113Wa 0812447359 | AllplanAttributes - Material: TI-1F-UZ-D; Codetext: Codetext; Türanschlag: DIN L; Attributset-Objekt: Door; Glasanteil_berücksichtigen: 100; ash T_Zulage Schachttür: no; ash T_Dichtschließend: no; ash T_Zarge_Typ: U; ash T_Erforderl. Durchgangsbreite: 0 m; ash T_Türblatt sichtbar 2D: ja; ash T_Feststellanlage (FSA): -; ash T_nicht abschließbar: no; ash T_Tür-Nr.: Innentür 1; ash T_Blatt_Oberfläche: -; ash T_Erford. Durgangshöhe: 0 m; ash T_Blatt_Material: -; ash T_Schallschutz: -; ash T_Zarge_Material: S; ash T_Raum zugehörigkeit: BS; Positionsnummer_Text: S68; Pset_OpeningElementCommon - FireExit: no; Reference: Codetext; DoorCommon - Außenliegend: no; Feuerwiderstandsklasse: EI2 30; Rauchschutz: yes; Selbstschließend: yes
SMT | H2 Ebene 0 | 1113Tür0812442210 | m² |  | Zimmer- und Holzbauarbeiten | Türmakro |  | 0 | NEW | 1113Wa 0812447359 | AllplanAttributes - Material: TI-1F-UZ-D; Codetext: Codetext; Türanschlag: DIN R; Attributset-Objekt: Door; Glasanteil_berücksichtigen: 100; ash T_Zulage Schachttür: no; ash T_Dichtschließend: no; ash T_Zarge_Typ: U; ash T_Erforderl. Durchgangsbreite: 0 m; ash T_Türblatt sichtbar 2D: ja; ash T_Feststellanlage (FSA): -; ash T_nicht abschließbar: no; ash T_Tür-Nr.: Innentür 1; ash T_Blatt_Oberfläche: -; ash T_Erford. Durgangshöhe: 0 m; ash T_Blatt_Material: -; ash T_Schallschutz: -; ash T_Zarge_Material: S; ash T_Raum zugehörigkeit: BS; Positionsnummer_Text: S68; Pset_OpeningElementCommon - FireExit: no; Reference: Codetext; DoorCommon - Außenliegend: no; Feuerwiderstandsklasse: EI2 30; Rauchschutz: yes; Selbstschließend: yes
SMT | H2 Ebene 0 | 1113Tür0814156805 | m² | 0 | Zimmer- und Holzbauarbeiten | Türöffnung | 0 |  | NEW | 1113Wa 0814156792 | AllplanAttributes - Türanschlag: DIN R
SMT | H2 Ebene 0 | 1113Tür0814156881 | m² | 0 | Zimmer- und Holzbauarbeiten | Türöffnung | 0 |  | NEW | 1113Wa 0814156792 | AllplanAttributes - Türanschlag: DIN L
Türöffnung | H2 Ebene 0 | 1113Tür0814119100 | m² |  | Zimmer- und Holzbauarbeiten | Türöffnung |  | 0 | NEW | 1113Wa 0814119137 | AllplanAttributes - Codetext: Codetext; Türanschlag: -; Attributset-Objekt: OpeningElement; Positionsnummer_Text: S68; Pset_OpeningElementCommon - FireExit: no; Reference: Codetext
Türöffnung | H2 Ebene 0 | 1113Tür0814119099 | m² | 0 | Zimmer- und Holzbauarbeiten | Türöffnung | 0 | 0 | NEW | 1113Wa 0814119142 | AllplanAttributes - Türanschlag: -; Positionsnummer_Text: S68
Türöffnung | H2 Ebene 0 | 1113Tür0814180090 | m² |  | Zimmer- und Holzbauarbeiten | Türöffnung |  | 0 | NEW | 1113Wa 0814180105 | AllplanAttributes - Codetext: Codetext; Türanschlag: -; Attributset-Objekt: OpeningElement; Positionsnummer_Text: S68; Pset_OpeningElementCommon - FireExit: no; Reference: Codetext
Türöffnung | H2 Ebene 0 | 1113Tür0814180111 | m² | 0 | Zimmer- und Holzbauarbeiten | Türöffnung | 0 | 0 | NEW | 1113Wa 0814180112 | AllplanAttributes - Türanschlag: -; Positionsnummer_Text: S68
Türöffnung | H2 Ebene 0 | 1113Tür0812438213 | m² |  | Zimmer- und Holzbauarbeiten | Türöffnung |  | 0 | NEW | 1113Wa 0812438228 | - | AllplanAttributes - Codetext: Codetext; Türanschlag: -; Attributset-Objekt: OpeningElement; Rauchschutz: no; Selbstschließend: no; ash T_Unterschnitt: -; ash T_Zulage Schachttür: no; ash T_Dichtschließend: yes; ash T_Feststellanlage (FSA): -; ash T_nicht abschließbar: no; Positionsnummer_Text: S68; Pset_OpeningElementCommon - FireExit: no; Reference: Codetext
Türöffnung | H2 Ebene 0 | 1113Tür0812438217 | m² |  | Zimmer- und Holzbauarbeiten | Türöffnung |  | 0 | NEW | 1113Wa 0812438228 | - | AllplanAttributes - Codetext: Codetext; Türanschlag: -; Attributset-Objekt: OpeningElement; Rauchschutz: no; Selbstschließend: no; ash T_Unterschnitt: -; ash T_Zulage Schachttür: no; ash T_Dichtschließend: yes; ash T_Feststellanlage (FSA): -; ash T_nicht abschließbar: no; Positionsnummer_Text: S68; Pset_OpeningElementCommon - FireExit: no; Reference: Codetext
Türöffnung | H2 Ebene 0 | 1113Tür0813141140 | m² | 0 | Zimmer- und Holzbauarbeiten | Türöffnung | 0 | 0 | NEW | 1113Wa 0813141038 | AllplanAttributes - Türanschlag: -; Positionsnummer_Text: S68
Türöffnung | H2 Ebene 0 | 1113Tür0813141048 | m² | 0 | Zimmer- und Holzbauarbeiten | Türöffnung | 0 | 0 | NEW | 1113Wa 0813141038 | AllplanAttributes - Türanschlag: -; Positionsnummer_Text: S68
Türöffnung | H2 Ebene 0 | 1113Tür0814138063 | m² |  | Zimmer- und Holzbauarbeiten | Türöffnung |  | 0 | NEW | 1113Wa 0814138083 | - | AllplanAttributes - Codetext: Codetext; Türanschlag: -; Attributset-Objekt: OpeningElement; Rauchschutz: no; Selbstschließend: no; ash T_Unterschnitt: -; ash T_Zulage Schachttür: no; ash T_Dichtschließend: yes; ash T_Feststellanlage (FSA): -; ash T_nicht abschließbar: no; Positionsnummer_Text: S68; Pset_OpeningElementCommon - FireExit: no; Reference: Codetext
Türöffnung | H2 Ebene 0 | 1113Tür0814138069 | m² |  | Zimmer- und Holzbauarbeiten | Türöffnung |  | 0 | NEW | 1113Wa 0814138083 | - | AllplanAttributes - Codetext: Codetext; Türanschlag: -; Attributset-Objekt: OpeningElement; Rauchschutz: no; Selbstschließend: no; ash T_Unterschnitt: -; ash T_Zulage Schachttür: no; ash T_Dichtschließend: yes; ash T_Feststellanlage (FSA): -; ash T_nicht abschließbar: no; Positionsnummer_Text: S68; Pset_OpeningElementCommon - FireExit: no; Reference: Codetext
Türöffnung | H2 Ebene 0 | 1113Tür0814138060 | m² | 0 | Zimmer- und Holzbauarbeiten | Türöffnung | 0 | 0 | NEW | 1113Wa 0814138081 | AllplanAttributes - Türanschlag: -; Positionsnummer_Text: S68
Türöffnung | H2 Ebene 0 | 1113Tür0814138061 | m² | 0 | Zimmer- und Holzbauarbeiten | Türöffnung | 0 | 0 | NEW | 1113Wa 0814138081 | AllplanAttributes - Türanschlag: -; Positionsnummer_Text: S68
Fensteröffnung | H2 Ebene 0 | 1113Fen0814280887 | m² |  | Trockenbauarbeiten | Fensteröffnung |  | 0 | NEW | 1113Wa 0814006150 | AllplanAttributes - W_Deckenanschluss: Gleitender Deckenanschluss Fall 01; Positionsnummer_Text: S68
Fensteröffnung | H2 Ebene 0 | 1113Fen0814021226 | m² |  | Fensterarbeiten | Fensteröffnung |  | 0 |  | 1113Wa 0814006150 | AllplanAttributes - W_Deckenanschluss: Gleitender Deckenanschluss Fall 01; Positionsnummer_Text: S68
Türöffnung | H2 Ebene 0 | 1113Tür0814186235 | m² |  | Zimmer- und Holzbauarbeiten | Türöffnung |  | 3.75 | NEW | 1113Wa 0814182742 | AllplanAttributes - Türanschlag: -; W_Deckenanschluss: Gleitender Deckenanschluss Fall 01; Positionsnummer_Text: U100
Türöffnung | H2 Ebene 0 | 1113Tür0812447092 | m² |  | Trockenbauarbeiten | Türöffnung |  | 0 | NEW | 1113Wa 0812447098 | AllplanAttributes - Bezeichnung: Türöffnung; Codetext: Codetext; Türanschlag: -; Attributset-Objekt: OpeningElement; W_Deckenanschluss: Gleitender Deckenanschluss Fall 01; Positionsnummer_Text: S68; Ortscode_Geschoßbezeichnung: E00; Pset_OpeningElementCommon - FireExit: no; Reference: Codetext
Türöffnung | H2 Ebene 0 | 1113Tür0812468447 | m² |  | Trockenbauarbeiten | Türöffnung |  | 0 | NEW | 1113Wa 0812468455 | AllplanAttributes - Bezeichnung: Türöffnung; Codetext: Codetext; Türanschlag: -; Attributset-Objekt: OpeningElement; W_Deckenanschluss: Gleitender Deckenanschluss Fall 01; Positionsnummer_Text: S68; Ortscode_Geschoßbezeichnung: E00; Pset_OpeningElementCommon - FireExit: no; Reference: Codetext
Türöffnung | H2 Ebene 0 | 1113Tür0812435739 | m² |  | Trockenbauarbeiten | Türöffnung |  | 0 | NEW | 1113Wa 0812447073 | AllplanAttributes - Bezeichnung: Türöffnung; Codetext: Codetext; Türanschlag: -; Attributset-Objekt: OpeningElement; W_Deckenanschluss: Gleitender Deckenanschluss Fall 01; Positionsnummer_Text: S68; Ortscode_Geschoßbezeichnung: E00; Pset_OpeningElementCommon - FireExit: no; Reference: Codetext
Türöffnung | H2 Ebene 0 | 1113Tür0812435698 | m² |  | Zimmer- und Holzbauarbeiten | Türöffnung |  | 0 | NEW | 1113Wa 0812447076 | AllplanAttributes - Material: TI-1F-UZ-ZK; Codetext: Codetext; Türanschlag: DIN R; Attributset-Objekt: OpeningElement; Positionsnummer_Text: S68; Pset_OpeningElementCommon - FireExit: no; Reference: Codetext
Türöffnung | H2 Ebene 0 | 1113Tür0813138134 | m² | 0 | Zimmer- und Holzbauarbeiten | Türöffnung | 0 | 0 | NEW | 1113Wa 0813138117 | AllplanAttributes - Material: TI-1F-UZ-ZK; Türanschlag: -; Positionsnummer_Text: S68
Türöffnung | H2 Ebene 0 | 1113Tür0812441811 | m² |  | Trockenbauarbeiten | Türöffnung |  | 0 | NEW | 1113Wa 0812441870 | AllplanAttributes - Bezeichnung: Türöffnung; Codetext: Codetext; Türanschlag: -; Attributset-Objekt: OpeningElement; Positionsnummer_Text: S68; Ortscode_Geschoßbezeichnung: E00; Pset_OpeningElementCommon - FireExit: no; Reference: Codetext
Türöffnung | H2 Ebene 0 | 1113Tür0813344581 | m² |  | Trockenbauarbeiten | Türöffnung |  | 0 | NEW | 1113Wa 0813344976 | AllplanAttributes - Türanschlag: -; W_Deckenanschluss: Gleitender Deckenanschluss Fall 01; Positionsnummer_Text: S68
Türöffnung | H2 Ebene 0 | 1113Tür0813243856 | m² |  | Zimmer- und Holzbauarbeiten | Türöffnung |  | 0 | NEW | 1113Wa 0813243858 | AllplanAttributes - Türanschlag: -; W_Deckenanschluss: Gleitender Deckenanschluss Fall 01; Positionsnummer_Text: S68
Türöffnung | H2 Ebene 0 | 1113Tür0812440699 | m² |  | Trockenbauarbeiten | Türöffnung |  | 0 | NEW | 1113Wa 0812440861 | AllplanAttributes - Türanschlag: -; W_Deckenanschluss: Gleitender Deckenanschluss Fall 01; Positionsnummer_Text: S68
Türöffnung | H2 Ebene 0 | 1113Tür0812440696 | m² |  | Zimmer- und Holzbauarbeiten | Türöffnung |  | 0 | NEW | 1113Wa 0812441727 | AllplanAttributes - Codetext: Codetext; Türanschlag: -; Attributset-Objekt: OpeningElement; Positionsnummer_Text: S68; Pset_OpeningElementCommon - FireExit: no; Reference: Codetext
Türöffnung | H2 Ebene 0 | 1113Tür0812440693 | m² |  | Zimmer- und Holzbauarbeiten | Türöffnung |  | 0 | NEW | 1113Wa 0812441727 | AllplanAttributes - Codetext: Codetext; Türanschlag: -; Attributset-Objekt: OpeningElement; Positionsnummer_Text: S68; Pset_OpeningElementCommon - FireExit: no; Reference: Codetext
Türöffnung | H2 Ebene 0 | 1113Tür0813137325 | m² | 0 | Zimmer- und Holzbauarbeiten | Türöffnung | 0 | 0 | NEW | 1113Wa 0813136637 | AllplanAttributes - Türanschlag: -; Positionsnummer_Text: S68
Türöffnung | H2 Ebene 0 | 1113Tür0813137233 | m² | 0 | Zimmer- und Holzbauarbeiten | Türöffnung | 0 | 0 | NEW | 1113Wa 0813136637 | AllplanAttributes - Türanschlag: -; Positionsnummer_Text: S68
Türöffnung | H2 Ebene 0 | 1113Tür0812508939 | m² |  | Zimmer- und Holzbauarbeiten | Türöffnung |  | 0 | NEW | 1113Wa 0812508669 | AllplanAttributes - Türanschlag: -; W_Deckenanschluss: Gleitender Deckenanschluss Fall 01; Positionsnummer_Text: S68
Türöffnung | H2 Ebene 0 | 1113Tür0812438947 | m² |  | Trockenbauarbeiten | Türöffnung |  | 0 | NEW | 1113Wa 0812440268 | AllplanAttributes - Türanschlag: -; W_Deckenanschluss: Gleitender Deckenanschluss Fall 01; Positionsnummer_Text: S68
Türöffnung | H2 Ebene 0 | 1113Tür0814139860 | m² |  | Zimmer- und Holzbauarbeiten | Türöffnung |  | 0 | NEW | 1113Wa 0814140000 | - | AllplanAttributes - Codetext: Codetext; Türanschlag: -; Attributset-Objekt: OpeningElement; Rauchschutz: no; Selbstschließend: no; ash T_Unterschnitt: -; ash T_Zulage Schachttür: no; ash T_Dichtschließend: yes; ash T_Feststellanlage (FSA): -; ash T_nicht abschließbar: no; Positionsnummer_Text: S68; Pset_OpeningElementCommon - FireExit: no; Reference: Codetext
Türöffnung | H2 Ebene 0 | 1113Tür0814139890 | m² | 0 | Zimmer- und Holzbauarbeiten | Türöffnung | 0 | 0 | NEW | 1113Wa 0814140005 | AllplanAttributes - Türanschlag: -; Positionsnummer_Text: S68
Türöffnung | H2 Ebene 0 | 1113Tür0812436063 | m² |  | Trockenbauarbeiten | Türöffnung |  | 0 | NEW | 1113Wa 0812437372 | AllplanAttributes - Türanschlag: -; W_Deckenanschluss: Gleitender Deckenanschluss Fall 01; Positionsnummer_Text: S68
Türöffnung | H2 Ebene 0 | 1113Tür0812523472 | m² |  | Zimmer- und Holzbauarbeiten | Türöffnung |  | 0 | NEW | 1113Wa 0812488027 | AllplanAttributes - Codetext: Codetext; Türanschlag: DIN L; Attributset-Objekt: OpeningElement; Positionsnummer_Text: S68; Pset_OpeningElementCommon - FireExit: no; Reference: Codetext
Türöffnung | H2 Ebene 0 | 1113Tür0813143280 | m² | 0 | Zimmer- und Holzbauarbeiten | Türöffnung | 0 | 0 | NEW | 1113Wa 0813143258 | AllplanAttributes - Türanschlag: DIN L; Positionsnummer_Text: S68
Türöffnung | H2 Ebene 0 | 1113Tür0813419470 | m² | 0 | Zimmer- und Holzbauarbeiten | Türöffnung | 0 | 0 | NEW | 1113Wa 0813419439 | AllplanAttributes - Türanschlag: DIN L; Positionsnummer_Text: S68
Türöffnung | H2 Ebene 0 | 1113Tür0813264838 | m² |  | Trockenbauarbeiten | Türöffnung |  | 0 | NEW | 1113Wa 0813264974 | AllplanAttributes - Türanschlag: -; W_Deckenanschluss: Gleitender Deckenanschluss Fall 01; Positionsnummer_Text: S68
Türöffnung | H2 Ebene 0 | 1113Tür0814130098 | m² |  | Zimmer- und Holzbauarbeiten | Türöffnung |  | 0 | NEW | 1113Wa 0814130111 | AllplanAttributes - Codetext: Codetext; Türanschlag: -; Attributset-Objekt: OpeningElement; Positionsnummer_Text: S68; Pset_OpeningElementCommon - FireExit: no; Reference: Codetext
Türöffnung | H2 Ebene 0 | 1113Tür0814130104 | m² |  | Zimmer- und Holzbauarbeiten | Türöffnung |  | 0 | NEW | 1113Wa 0814130111 | - | AllplanAttributes - Codetext: Codetext; Türanschlag: -; Attributset-Objekt: OpeningElement; Rauchschutz: no; Selbstschließend: no; ash T_Unterschnitt: -; ash T_Zulage Schachttür: no; ash T_Dichtschließend: yes; ash T_Feststellanlage (FSA): -; ash T_nicht abschließbar: no; Positionsnummer_Text: S68; Pset_OpeningElementCommon - FireExit: no; Reference: Codetext
Türöffnung | H2 Ebene 0 | 1113Tür0814130103 | m² | 0 | Zimmer- und Holzbauarbeiten | Türöffnung | 0 | 0 | NEW | 1113Wa 0814130109 | AllplanAttributes - Türanschlag: -; Positionsnummer_Text: S68
Türöffnung | H2 Ebene 0 | 1113Tür0814130097 | m² | 0 | Zimmer- und Holzbauarbeiten | Türöffnung | 0 | 0 | NEW | 1113Wa 0814130109 | AllplanAttributes - Türanschlag: -; Positionsnummer_Text: S68
Türöffnung | H2 Ebene 0 | 1113Tür0812551339 | m² |  | Zimmer- und Holzbauarbeiten | Türöffnung |  | 0 | NEW | 1113Wa 0812551342 | AllplanAttributes - Codetext: Codetext; Türanschlag: DIN L; Attributset-Objekt: OpeningElement; Positionsnummer_Text: S68; Pset_OpeningElementCommon - FireExit: no; Reference: Codetext
Türöffnung | H2 Ebene 0 | 1113Tür0813854354 | m² |  | Zimmer- und Holzbauarbeiten | Türöffnung |  | 0 |  | 1113Wa 0813854360 | AllplanAttributes - Codetext: Codetext; Türanschlag: -; Positionsnummer_Text: S68; Pset_OpeningElementCommon - FireExit: no; Reference: Codetext
Türöffnung | H2 Ebene 0 | 1113Tür0812435720 | m² |  | Trockenbauarbeiten | Türöffnung |  | 0 | NEW | 1113Wa 0812444170 | AllplanAttributes - Codetext: Codetext; Türanschlag: -; Attributset-Objekt: OpeningElement; W_Deckenanschluss: Gleitender Deckenanschluss Fall 01; Positionsnummer_Text: S68; Pset_OpeningElementCommon - FireExit: no; Reference: Codetext
Türöffnung | H2 Ebene 0 | 1113Tür0812516233 | m² |  | Trockenbauarbeiten | Türöffnung |  | 0 | NEW | 1113Wa 0812516237 | AllplanAttributes - Codetext: Codetext; Türanschlag: -; Attributset-Objekt: OpeningElement; W_Deckenanschluss: Gleitender Deckenanschluss Fall 01; Positionsnummer_Text: S68; Pset_OpeningElementCommon - FireExit: no; Reference: Codetext
Türöffnung | H2 Ebene 0 | 1113Tür0812438669 | m² |  | Trockenbauarbeiten | Türöffnung |  | 0 | NEW | 1113Wa 0812439875 | AllplanAttributes - Codetext: Codetext; Türanschlag: -; Attributset-Objekt: OpeningElement; W_Deckenanschluss: Gleitender Deckenanschluss Fall 01; Positionsnummer_Text: S68; Pset_OpeningElementCommon - FireExit: no; Reference: Codetext
Türöffnung | H2 Ebene 0 | 1113Tür0812524520 | m² |  | Trockenbauarbeiten | Türöffnung |  | 0 | NEW | 1113Wa 0812524524 | AllplanAttributes - Codetext: Codetext; Türanschlag: -; Attributset-Objekt: OpeningElement; W_Deckenanschluss: Gleitender Deckenanschluss Fall 01; Positionsnummer_Text: S68; Pset_OpeningElementCommon - FireExit: no; Reference: Codetext
Türöffnung | H2 Ebene 0 | 1113Tür0813393505 | m² |  | Zimmer- und Holzbauarbeiten | Türöffnung |  | 0 | NEW | 1113Wa 0813393511 | AllplanAttributes - Türanschlag: -; Positionsnummer_Text: S68
Fensteröffnung | H2 Ebene 0 | 1113Fen0813940717 | m² |  | Fensterarbeiten | Fensteröffnung |  | 0 |  | 1113Wa 0813940656 | AllplanAttributes - ash D_Detailverweis: D1833; Positionsnummer_Text: S68
Türöffnung | H2 Ebene 0 | 1113Tür0812480017 | m² |  | Zimmer- und Holzbauarbeiten | Türöffnung |  | 0 |  | 1113Wa 0812440294 | AllplanAttributes - Bezeichnung: Türöffnung; Codetext: Codetext; Türanschlag: -; Positionsnummer_Text: S68; Pset_OpeningElementCommon - FireExit: no; Reference: Codetext
Türöffnung | H2 Ebene 0 | 1113Tür0812447345 | m² |  | Zimmer- und Holzbauarbeiten | Türöffnung |  | 0 | NEW | 1113Wa 0812447378 | AllplanAttributes - Codetext: Codetext; Türanschlag: DIN R; Attributset-Objekt: OpeningElement; Positionsnummer_Text: S68; Pset_OpeningElementCommon - FireExit: no; Reference: Codetext
Türöffnung | H2 Ebene 0 | 1113Tür0812888851 | m² | 0 | Zimmer- und Holzbauarbeiten | Türöffnung | 0 | 0 | NEW | 1113Wa 0812888839 | AllplanAttributes - Türanschlag: DIN R; Positionsnummer_Text: S68
Türöffnung | H2 Ebene 0 | 1113Tür0814156324 | m² | 0 | Zimmer- und Holzbauarbeiten | Türöffnung | 0 |  | NEW | 1113Wa 0814156308 | AllplanAttributes - Türanschlag: DIN R
Türöffnung | H2 Ebene 0 | 1113Tür0812517822 | m² |  | Zimmer- und Holzbauarbeiten | Türöffnung |  | 0 | NEW | 1113Wa 0812446937 | AllplanAttributes - Bezeichnung: Türöffnung; Türanschlag: -; Positionsnummer_Text: S68
Türöffnung | H2 Ebene 0 | 1113Tür0813370553 | m² |  | Zimmer- und Holzbauarbeiten | Türöffnung |  | 0 | NEW | 1113Wa 0813370687 | AllplanAttributes - Bezeichnung: Türöffnung; Türanschlag: -; Positionsnummer_Text: S68
Türöffnung | H2 Ebene 0 | 1113Tür0812440004 | m² |  | Zimmer- und Holzbauarbeiten | Türöffnung |  | 0 | NEW | 1113Wa 0812440009 | REI 90-A1 | AllplanAttributes - Material: WA-STB; Tragendes Bauteil: yes; Brandabschnittsdefinierendes Bauteil: no; Außenliegend: yes; U-Wert: 0; Schallschutzklasse: 0; Bezeichnung: Türöffnung; Codetext: Codetext; Türanschlag: -; Typ: 0; Brennbares Material: no; Brandverhalten: 0; Brandschutzklasse: A; Positionsnummer_Text: S68; Pset_OpeningElementCommon - Reference: Codetext
Fensteröffnung | H2 Ebene 0 | 1113Fen0812934772 | m² |  | Fensterarbeiten | Fensteröffnung |  | 0 |  | 1113Wa 0812934445 | AllplanAttributes - W_Deckenanschluss: Gleitender Deckenanschluss Fall 01; Positionsnummer_Text: S68
Türöffnung | H2 Ebene 0 | 1113Tür0812934703 | m² | 0 | Zimmer- und Holzbauarbeiten | Türöffnung | 0 | 0 | NEW | 1113Wa 0812934445 | REI 90-A1 | AllplanAttributes - Material: WA-STB; Tragendes Bauteil: yes; Brandabschnittsdefinierendes Bauteil: no; Außenliegend: yes; U-Wert: 0; Schallschutzklasse: 0; Codetext: Codetext; Türanschlag: -; Typ: 0; Brennbares Material: no; Brandverhalten: 0; Brandschutzklasse: A; W_Deckenanschluss: Gleitender Deckenanschluss Fall 01; Positionsnummer_Text: S68; Pset_OpeningElementCommon - Reference: Codetext
Fensteröffnung | H2 Ebene 0 | 1113Fen0812935048 | m² |  | Fensterarbeiten | Fensteröffnung |  | 0 |  | 1113Wa 0812934445 | AllplanAttributes - Bezeichnung: Fensteröffnung; W_Deckenanschluss: Gleitender Deckenanschluss Fall 01; Positionsnummer_Text: S68
Türöffnung | H2 Ebene 0 | 1113Tür0812441058 | m² |  | Trockenbauarbeiten | Türöffnung |  | 0 | NEW | 1113Wa 0812441640 | AllplanAttributes - Bezeichnung: Türöffnung; Codetext: Codetext; Türanschlag: -; Attributset-Objekt: OpeningElement; Positionsnummer_Text: S68; Ortscode_Geschoßbezeichnung: E00; Pset_OpeningElementCommon - FireExit: no; Reference: Codetext
Türöffnung | H2 Ebene 0 | 1113Tür0812440948 | m² |  | Trockenbauarbeiten | Türöffnung |  | 0 | NEW | 1113Wa 0812441691 | AllplanAttributes - Bezeichnung: Türöffnung; Codetext: Codetext; Türanschlag: -; Attributset-Objekt: OpeningElement; Positionsnummer_Text: S68; Ortscode_Geschoßbezeichnung: E00; Pset_OpeningElementCommon - FireExit: no; Reference: Codetext
Türöffnung | H2 Ebene 0 | 1113Tür0812441168 | m² |  | Trockenbauarbeiten | Türöffnung |  | 0 | NEW | 1113Wa 0812441637 | AllplanAttributes - Bezeichnung: Türöffnung; Codetext: Codetext; Türanschlag: -; Attributset-Objekt: OpeningElement; Positionsnummer_Text: S68; Ortscode_Geschoßbezeichnung: E00; Pset_OpeningElementCommon - FireExit: no; Reference: Codetext
Türöffnung | H2 Ebene 0 | 1113Tür0812441278 | m² |  | Trockenbauarbeiten | Türöffnung |  | 0 | NEW | 1113Wa 0812441694 | AllplanAttributes - Bezeichnung: Türöffnung; Codetext: Codetext; Türanschlag: -; Attributset-Objekt: OpeningElement; Positionsnummer_Text: S68; Ortscode_Geschoßbezeichnung: E00; Pset_OpeningElementCommon - FireExit: no; Reference: Codetext
Türöffnung | H2 Ebene 0 | 1113Tür0814025280 | m² | 0 | Zimmer- und Holzbauarbeiten | Türöffnung | 0 | 0 | NEW | 1113Wa 0814024952 | AllplanAttributes - Türanschlag: DIN R; Positionsnummer_Text: S68
2 x Türöffnung | H2 Ebene 0 | 1113Tür0814025278 | m² | -30 | Zimmer- und Holzbauarbeiten | Türöffnung | 0 |  | NEW | 1113Wa 0814024953 | AllplanAttributes - Türanschlag: DIN R
Türöffnung | H2 Ebene 0 | 1113Tür0814025279 | m² | 0 | Zimmer- und Holzbauarbeiten | Türöffnung | 0 |  | NEW | 1113Wa 0814024953 | AllplanAttributes - Türanschlag: DIN R
Wandnische | H2 Ebene 0 | 1113Wni0814255155 | m² | 0 | Zimmer- und Holzbauarbeiten | Wandnische | 0 |  | NEW
Türöffnung | H2 Ebene 0 | 1113Tür0814166076 | m² |  | Trockenbauarbeiten | Türöffnung |  | 0 | NEW | 1113Wa 0814166079 | AllplanAttributes - Codetext: Codetext; Türanschlag: DIN R; Attributset-Objekt: OpeningElement; Positionsnummer_Text: S68; ash_W_Trockenbau_Qualitäten: 8; Pset_OpeningElementCommon - FireExit: no; Reference: Codetext
Türöffnung | H2 Ebene 0 | 1113Tür0814166046 | m² | 0 | Trockenbauarbeiten | Türöffnung | 0 | 0 | NEW | 1113Wa 0814166082 | AllplanAttributes - Türanschlag: DIN R; Positionsnummer_Text: S68
Türöffnung | H2 Ebene 0 | 1113Tür0812442292 | m² |  | Zimmer- und Holzbauarbeiten | Türöffnung |  | 0 | NEW | 1113Wa 0812443005 | AllplanAttributes - Codetext: Codetext; Türanschlag: DIN R; Attributset-Objekt: OpeningElement; Positionsnummer_Text: S68; ash_W_Trockenbau_Qualitäten: 8; Pset_OpeningElementCommon - FireExit: no; Reference: Codetext
Türöffnung | H2 Ebene 0 | 1113Tür0813117543 | m² | 0 | Zimmer- und Holzbauarbeiten | Türöffnung | 0 | 0 | NEW | 1113Wa 0813117404 | AllplanAttributes - Türanschlag: DIN R; Positionsnummer_Text: S68
Türöffnung | H2 Ebene 0 | 1113Tür0814179249 | m² |  | Zimmer- und Holzbauarbeiten | Türöffnung |  | 0 | NEW | 1113Wa 0814179261 | AllplanAttributes - Codetext: Codetext; Türanschlag: DIN L; Attributset-Objekt: OpeningElement; Positionsnummer_Text: S68; ash_W_Trockenbau_Qualitäten: 8; Pset_OpeningElementCommon - FireExit: no; Reference: Codetext
Türöffnung | H2 Ebene 0 | 1113Tür0814179248 | m² | 0 | Zimmer- und Holzbauarbeiten | Türöffnung | 0 | 0 | NEW | 1113Wa 0814179263 | AllplanAttributes - Türanschlag: DIN L; Positionsnummer_Text: S68
Türöffnung | H2 Ebene 0 | 1113Tür0814233851 | m² |  | Zimmer- und Holzbauarbeiten | Türöffnung |  | 0 | NEW | 1113Wa 0812551363 | AllplanAttributes - Codetext: Codetext; Türanschlag: DIN L; Attributset-Objekt: OpeningElement; Positionsnummer_Text: S68; ash_W_Trockenbau_Qualitäten: 8; Pset_OpeningElementCommon - FireExit: no; Reference: Codetext
Türöffnung | H2 Ebene 0 | 1113Tür0814233858 | m² | 0 | Zimmer- und Holzbauarbeiten | Türöffnung | 0 | 0 | NEW | 1113Wa 0813421529 | AllplanAttributes - Türanschlag: DIN L; Positionsnummer_Text: S68
Türöffnung | H2 Ebene 0 | 1113Tür0812551380 | m² |  | Metallbau-, Schlosserarbeiten | Türmakro |  | 0 | NEW | 1113Wa 0812551371 | AllplanAttributes - Material: TI-1F-UZ-D; Codetext: Codetext; Türanschlag: DIN R; Attributset-Objekt: Door; Positionsnummer: 1; V6: 0 m; V7: 0 m; V8: 0 m; V9: 0; Glasanteil_berücksichtigen: 100; ash T_Unterschnitt: -; ash T_Zulage Schachttür: no; ash T_Dichtschließend: yes; ash T_Zarge_Typ: U; ash T_Erforderl. Durchgangsbreite: 0 m; ash T_Türblatt sichtbar 2D: ja; ash T_Feststellanlage (FSA): -; ash T_nicht abschließbar: no; ash T_Blatt_Oberfläche: -; ash T_Erford. Durgangshöhe: 0 m; ash T_Blatt_Material: -; ash T_Schallschutz: -; ash T_Zarge_Material: S; ash T_Raum zugehörigkeit: BS; Positionsnummer_Text: S68; Pset_OpeningElementCommon - FireExit: no; Reference: Codetext; DoorCommon - Außenliegend: no; Feuerwiderstandsklasse: -; Rauchschutz: no; Selbstschließend: no
Türöffnung | H2 Ebene 0 | 1113Tür0813421766 | m² | 0 | Metallbau-, Schlosserarbeiten | Türöffnung | 0 | 0 | NEW | 1113Wa 0813421754 | AllplanAttributes - Türanschlag: DIN R; Positionsnummer_Text: S68; ash_W_Trockenbau_Qualitäten: 8
Türöffnung | H2 Ebene 0 | 1113Tür0813017166 | m² |  | Trockenbauarbeiten | Türöffnung |  | 0 | NEW | 1113Wa 0813017169 | AllplanAttributes - Codetext: Codetext; Türanschlag: -; Attributset-Objekt: OpeningElement; W_Deckenanschluss: Gleitender Deckenanschluss Fall 01; Positionsnummer_Text: S68; Pset_OpeningElementCommon - FireExit: no; Reference: Codetext
Türöffnung | H2 Ebene 0 | 1113Tür0812435823 | m² |  | Trockenbauarbeiten | Türöffnung |  | 0 | NEW | 1113Wa 0812442543 | AllplanAttributes - Codetext: Codetext; Türanschlag: -; Attributset-Objekt: OpeningElement; W_Deckenanschluss: Gleitender Deckenanschluss Fall 01; Positionsnummer_Text: S68; Pset_OpeningElementCommon - FireExit: no; Reference: Codetext
Türöffnung | H2 Ebene 0 | 1113Tür0814242336 | m² | 0 | Zimmer- und Holzbauarbeiten | Türöffnung | 0 | 0 | NEW | 1113Wa 0814209589 | AllplanAttributes - Schallschutzklasse: 47; Codetext: Codetext; Türanschlag: DIN R; Attributset-Objekt: OpeningElement; Positionsnummer_Text: S68; Pset_OpeningElementCommon - FireExit: no; Reference: Codetext
Türöffnung | H2 Ebene 0 | 1113Tür0814242335 | m² | 0 | Zimmer- und Holzbauarbeiten | Türöffnung | 0 | 0 | NEW | 1113Wa 0814209583 | AllplanAttributes - Schallschutzklasse: 47; Türanschlag: DIN R; Positionsnummer_Text: S68
Türöffnung | H2 Ebene 0 | 1113Tür0814242334 | m² | 0 | Zimmer- und Holzbauarbeiten | Türöffnung | 0 | 0 | NEW | 1113Wa 0814209584 | AllplanAttributes - Schallschutzklasse: 47; Türanschlag: DIN R; Positionsnummer_Text: S68
Türöffnung | H2 Ebene 0 | 1113Tür0812543259 | m² |  | Zimmer- und Holzbauarbeiten | Türöffnung |  | 0 | NEW | 1113Wa 0812543262 | AllplanAttributes - Codetext: Codetext; Türanschlag: DIN L; Attributset-Objekt: OpeningElement; Positionsnummer_Text: S68; Pset_OpeningElementCommon - FireExit: no; Reference: Codetext
Türöffnung | H2 Ebene 0 | 1113Tür0813129560 | m² | 0 | Zimmer- und Holzbauarbeiten | Türöffnung | 0 | 0 | NEW | 1113Wa 0813129542 | AllplanAttributes - Türanschlag: DIN L; Positionsnummer_Text: S68
Türöffnung | H2 Ebene 0 | 1113Tür0813129561 | m² | 0 | Zimmer- und Holzbauarbeiten | Türöffnung | 0 | 0 | NEW | 1113Wa 0813129543 | AllplanAttributes - Türanschlag: DIN L; Positionsnummer_Text: S68
Fensteröffnung | H2 Ebene 0 | 1113Fen0812435743 | m² |  | Fensterarbeiten | Fensteröffnung |  | 0 |  | 1113Wa 0812437264 | AllplanAttributes - Positionsnummer_Text: S68
Fensteröffnung | H2 Ebene 0 | 1113Fen0813139945 | m² | 0 | Fensterarbeiten | Fensteröffnung | 0 | 0 | NEW | 1113Wa 0813139914 | AllplanAttributes - Positionsnummer_Text: S68
Fensteröffnung | H2 Ebene 0 | 1113Fen0813139946 | m² | 0 | Fensterarbeiten | Fensteröffnung | 0 | 0 | NEW | 1113Wa 0813139915 | AllplanAttributes - ash D_Detailverweis: D1833; Positionsnummer_Text: S68
Türöffnung | H2 Ebene 0 | 1113Tür0813937079 | m² | 0 | Zimmer- und Holzbauarbeiten | Türöffnung | 0 | 0 | NEW | 1113Wa 0813453141 | E 60 | AllplanAttributes - Türanschlag: -; Text1: 15b; Positionsnummer_Text: S68
Türöffnung | H2 Ebene 0 | 1113Tür0813931968 | m² | 0 | Zimmer- und Holzbauarbeiten | Türöffnung | 0 | 0 | NEW | 1113Wa 0813453141 | E 60 | AllplanAttributes - Türanschlag: -; Text1: 15b; Positionsnummer_Text: S68
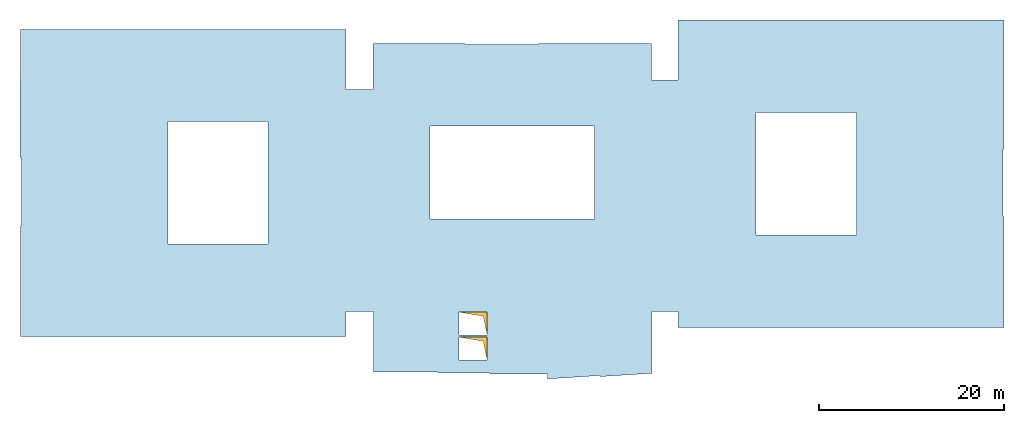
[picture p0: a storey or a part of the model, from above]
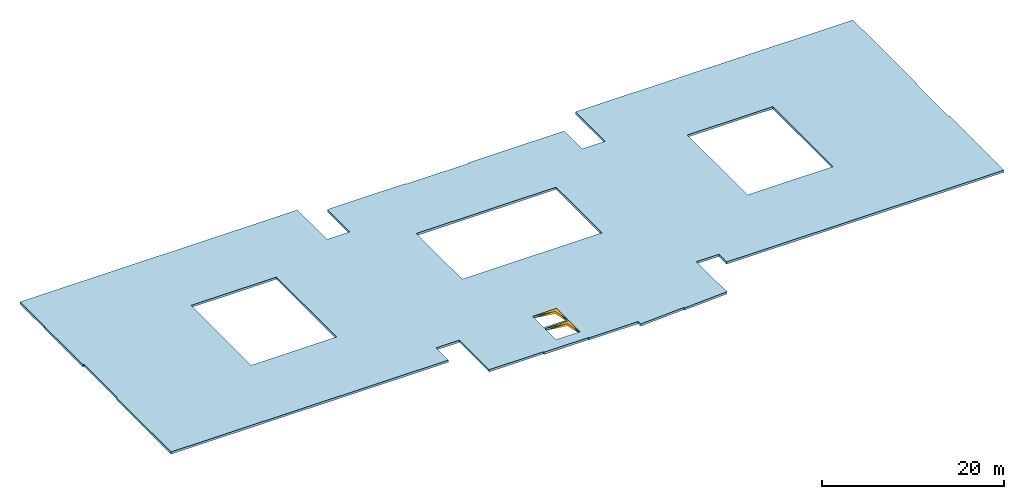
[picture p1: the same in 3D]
Properties of the parts of a building model (IFC4), part 43 of 80

# IfcOpeningElement: Opening (3497)
Name | In | Allright_Bauteil_ID | Abrechnungsart | Versatz_oben | Gewerk | Objektname | Versatz_unten | OKFF | Status | P_ID | AllplanAttributes, Feuerwiderstandsklasse | Sicherheitsklasse | g-Wert
Türöffnung | H2 Ebene 0 | 1113Tür0813453127 | m² |  | Trockenbauarbeiten | Türöffnung |  | 0 | NEW | 1113Wa 0813453141 | EI2 30 | AllplanAttributes - Codetext: Codetext; Türanschlag: DIN R; Attributset-Objekt: OpeningElement; Rauchschutz: yes; Selbstschließend: yes; ash T_Zulage Schachttür: no; ash T_Dichtschließend: no; ash T_Feststellanlage (FSA): -; ash T_nicht abschließbar: no; Positionsnummer_Text: S68; Pset_OpeningElementCommon - FireExit: no; Reference: Codetext
Türöffnung | H2 Ebene 0 | 1113Tür0813931967 | m² | -170 | Zimmer- und Holzbauarbeiten | Türöffnung | 0 | 0 | NEW | 1113Wa 0813453140 | AllplanAttributes - Türanschlag: -; Positionsnummer_Text: S68
Türöffnung | H2 Ebene 0 | 1113Tür0813453126 | m² | 0 | Trockenbauarbeiten | Türöffnung | 0 | 0 | NEW | 1113Wa 0813453140 | AllplanAttributes - Türanschlag: DIN R; Positionsnummer_Text: S68
Türöffnung | H2 Ebene 0 | 1113Tür0813937078 | m² | -170 | Zimmer- und Holzbauarbeiten | Türöffnung | 0 | 0 | NEW | 1113Wa 0813453140 | AllplanAttributes - Türanschlag: -; Positionsnummer_Text: S68
Türöffnung | H2 Ebene 0 | 1113Tür0812553540 | m² |  | Zimmer- und Holzbauarbeiten | Türöffnung |  | 0 | NEW | 1113Wa 0812553865 | AllplanAttributes - Codetext: Codetext; Türanschlag: DIN R; Attributset-Objekt: OpeningElement; Positionsnummer_Text: S68; Pset_OpeningElementCommon - FireExit: no; Reference: Codetext
Türöffnung | H2 Ebene 0 | 1113Tür0812553538 | m² |  | Zimmer- und Holzbauarbeiten | Türöffnung |  | 0 | NEW | 1113Wa 0812553865 | AllplanAttributes - Codetext: Codetext; Türanschlag: DIN R; Attributset-Objekt: OpeningElement; Positionsnummer_Text: S68; Pset_OpeningElementCommon - FireExit: no; Reference: Codetext
Türöffnung | H2 Ebene 0 | 1113Tür0813418703 | m² | 0 | Zimmer- und Holzbauarbeiten | Türöffnung | 0 | 0 | NEW | 1113Wa 0813418548 | AllplanAttributes - Türanschlag: DIN R; Positionsnummer_Text: S68; ash_W_Trockenbau_Qualitäten: 8
Türöffnung | H2 Ebene 0 | 1113Tür0813418582 | m² | 0 | Zimmer- und Holzbauarbeiten | Türöffnung | 0 | 0 | NEW | 1113Wa 0813418548 | AllplanAttributes - Türanschlag: DIN R; Positionsnummer_Text: S68; ash_W_Trockenbau_Qualitäten: 8
Türöffnung | H2 Ebene 0 | 1113Tür0813946269 | m² | 0 | Zimmer- und Holzbauarbeiten | Türöffnung | 0 | 0 | NEW | 1113Wa 0813936885 | AllplanAttributes - Codetext: Codetext; Türanschlag: DIN R; Attributset-Objekt: OpeningElement; Positionsnummer_Text: S68; Pset_OpeningElementCommon - FireExit: no; Reference: Codetext
Türöffnung | H2 Ebene 0 | 1113Tür0813946270 | m² | 0 | Zimmer- und Holzbauarbeiten | Türöffnung | 0 | 0 | NEW | 1113Wa 0813936886 | AllplanAttributes - Türanschlag: DIN R; Positionsnummer_Text: S68; ash_W_Trockenbau_Qualitäten: 8
Türöffnung | H2 Ebene 0 | 1113Tür0812435737 | m² |  | Zimmer- und Holzbauarbeiten | Türöffnung |  | 0 | NEW | 1113Wa 0812447118 | AllplanAttributes - Codetext: Codetext; Türanschlag: DIN R; Attributset-Objekt: OpeningElement; Positionsnummer_Text: S68; Pset_OpeningElementCommon - FireExit: no; Reference: Codetext
Türöffnung | H2 Ebene 0 | 1113Tür0813125570 | m² | 0 | Zimmer- und Holzbauarbeiten | Türöffnung | 0 | 0 | NEW | 1113Wa 0813125542 | AllplanAttributes - Türanschlag: DIN R; Positionsnummer_Text: S68
Türöffnung | H2 Ebene 0 | 1113Tür0813125571 | m² | 0 | Zimmer- und Holzbauarbeiten | Türöffnung | 0 | 0 | NEW | 1113Wa 0813125543 | AllplanAttributes - Türanschlag: DIN R; Positionsnummer_Text: S68
Türöffnung | H2 Ebene 0 | 1113Tür0814194992 | m² |  | Zimmer- und Holzbauarbeiten | Türöffnung |  | 3.75 | NEW | 1113Wa 0814190817 | AllplanAttributes - Türanschlag: -; W_Deckenanschluss: Gleitender Deckenanschluss Fall 01; Positionsnummer_Text: U100
Fensteröffnung | H2 Ebene 0 | 1113Fen0814189290 | m² |  | Fensterarbeiten | Fensteröffnung |  | 0 |  | 1113Wa 0814188404 | AllplanAttributes - Positionsnummer_Text: S68
Fensteröffnung | H2 Ebene 0 | 1113Fen0814233613 | m² | 0 | Fensterarbeiten | Fensteröffnung | 0 | 0 |  | 1113Wa 0814188404 | AllplanAttributes - Positionsnummer_Text: S68
Fensteröffnung | H2 Ebene 0 | 1113Fen0814215040 | m² |  | Fensterarbeiten | Fensteröffnung |  | 0 |  | 1113Wa 0814188404 | AllplanAttributes - Positionsnummer_Text: S68
Türöffnung | H2 Ebene 0 | 1113Tür0812446813 | m² |  | Zimmer- und Holzbauarbeiten | Türöffnung |  | 0 | NEW | 1113Wa 0812446823 | AllplanAttributes - Codetext: Codetext; Türanschlag: DIN L; Attributset-Objekt: OpeningElement; Positionsnummer_Text: S68; Pset_OpeningElementCommon - FireExit: no; Reference: Codetext
Türöffnung | H2 Ebene 0 | 1113Tür0813128762 | m² | 0 | Zimmer- und Holzbauarbeiten | Türöffnung | 0 | 0 | NEW | 1113Wa 0813128732 | AllplanAttributes - Türanschlag: DIN L; Positionsnummer_Text: S68
Türöffnung | H2 Ebene 0 | 1113Tür0813129172 | m² | 0 | Zimmer- und Holzbauarbeiten | Türöffnung | 0 | 0 | NEW | 1113Wa 0813129129 | AllplanAttributes - Türanschlag: DIN L; Positionsnummer_Text: S68
Türöffnung | H2 Ebene 0 | 1113Tür0812551337 | m² |  | Zimmer- und Holzbauarbeiten | Türöffnung |  | 0 | NEW | 1113Wa 0812551376 | AllplanAttributes - Codetext: Codetext; Türanschlag: DIN L; Attributset-Objekt: OpeningElement; Positionsnummer_Text: S68; Pset_OpeningElementCommon - FireExit: no; Reference: Codetext
Türöffnung | H2 Ebene 0 | 1113Tür0813119673 | m² | 0 | Zimmer- und Holzbauarbeiten | Türöffnung | 0 | 0 | NEW | 1113Wa 0813119660 | AllplanAttributes - Türanschlag: DIN L; Positionsnummer_Text: S68; ash_W_Trockenbau_Qualitäten: 8
Türöffnung | H2 Ebene 0 | 1113Tür0814187186 | m² |  | Zimmer- und Holzbauarbeiten | Türöffnung |  | 0 | NEW | 1113Wa 0814187216 | - | AllplanAttributes - Codetext: Codetext; Türanschlag: -; Attributset-Objekt: OpeningElement; Rauchschutz: no; Selbstschließend: no; ash T_Unterschnitt: -; ash T_Zulage Schachttür: no; ash T_Dichtschließend: yes; ash T_Feststellanlage (FSA): -; ash T_nicht abschließbar: no; Positionsnummer_Text: S68; Pset_OpeningElementCommon - FireExit: no; Reference: Codetext
Türöffnung | H2 Ebene 0 | 1113Tür0814187260 | m² | 0 | Zimmer- und Holzbauarbeiten | Türöffnung | 0 |  | NEW | 1113Wa 0814187250 | AllplanAttributes - Türanschlag: -
Türöffnung | H2 Ebene 0 | 1113Tür0812436843 | m² |  | Trockenbauarbeiten | Türöffnung |  | 0 | NEW | 1113Wa 0812438246 | AllplanAttributes - Bezeichnung: Türöffnung; Codetext: Codetext; Türanschlag: -; Attributset-Objekt: OpeningElement; W_Deckenanschluss: Gleitender Deckenanschluss Fall 01; Positionsnummer_Text: S68; Ortscode_Geschoßbezeichnung: E00; Pset_OpeningElementCommon - FireExit: no; Reference: Codetext
Fensteröffnung | H2 Ebene 0 | 1113Fen0814280888 | m² |  | Tischlerarbeiten | Fensteröffnung |  | 0 | NEW | 1113Wa 0814006162 | AllplanAttributes - W_Deckenanschluss: Gleitender Deckenanschluss Fall 01; Positionsnummer_Text: S68
Fensteröffnung | H2 Ebene 0 | 1113Fen0814190707 | m² |  | Fensterarbeiten | Fensteröffnung |  | 0 |  | 1113Wa 0814190720 | AllplanAttributes - W_Deckenanschluss: Gleitender Deckenanschluss Fall 01; Positionsnummer_Text: S68
Fensteröffnung | H2 Ebene 0 | 1113Fen0814266528 | m² |  | Fensterarbeiten | Fensteröffnung |  | 0 |  | 1113Wa 0814190720 | AllplanAttributes - W_Deckenanschluss: Gleitender Deckenanschluss Fall 01; Positionsnummer_Text: S68
Fensteröffnung | H2 Ebene 0 | 1113Fen0814281137 | m² |  | Fensterarbeiten | Fensteröffnung |  | 0 |  | 1113Wa 0814190720 | AllplanAttributes - W_Deckenanschluss: Gleitender Deckenanschluss Fall 01; Positionsnummer_Text: S68
Türöffnung | H2 Ebene 0 | 1113Tür0814281642 | m² | 0 | Zimmer- und Holzbauarbeiten | Türöffnung | 0 | 0 | NEW | 1113Wa 0813218101 | REI 90-A1 | AllplanAttributes - Material: WA-STB; Tragendes Bauteil: yes; Brandabschnittsdefinierendes Bauteil: no; Außenliegend: yes; U-Wert: 0; Schallschutzklasse: 0; Codetext: Codetext; Türanschlag: -; Typ: 0; Brennbares Material: no; Brandverhalten: 0; Brandschutzklasse: A; W_Deckenanschluss: Gleitender Deckenanschluss Fall 01; Positionsnummer_Text: S68; Text4: Stahl-Glas-Tür; Pset_OpeningElementCommon - Reference: Codetext
Türöffnung | H2 Ebene 0 | 1113Tür0812446140 | m² |  | Betonarbeiten | Türöffnung |  | 0 | NEW | 1113Wa 0812446151 | REI 90-A1 | AllplanAttributes - Material: WA-STB; Tragendes Bauteil: yes; Brandabschnittsdefinierendes Bauteil: no; Außenliegend: yes; U-Wert: 0; Schallschutzklasse: 0; Codetext: Codetext; Türanschlag: -; Typ: 0; Brennbares Material: no; Brandverhalten: 0; Brandschutzklasse: A; W_Deckenanschluss: Gleitender Deckenanschluss Fall 01; Positionsnummer_Text: S68; Pset_OpeningElementCommon - Reference: Codetext
Türöffnung | H2 Ebene 0 | 1113Tür0812438673 | m² |  | Betonarbeiten | Türöffnung |  | 0 | NEW | 1113Wa 0812438684 | REI 90-A1 | AllplanAttributes - Material: WA-STB; Tragendes Bauteil: yes; Brandabschnittsdefinierendes Bauteil: no; Außenliegend: yes; U-Wert: 0; Schallschutzklasse: 0; Codetext: Codetext; Türanschlag: -; Typ: 0; Brennbares Material: no; Brandverhalten: 0; Brandschutzklasse: A; W_Deckenanschluss: Gleitender Deckenanschluss Fall 01; Positionsnummer_Text: S68; Pset_OpeningElementCommon - Reference: Codetext
Türöffnung | H2 Ebene 0 | 1113Tür0814282830 | m² |  | Zimmer- und Holzbauarbeiten | Türöffnung |  | 0 | NEW | 1113Wa 0812889012 | AllplanAttributes - Codetext: Codetext; Türanschlag: DIN L; Attributset-Objekt: OpeningElement; Positionsnummer_Text: S68; Pset_OpeningElementCommon - FireExit: no; Reference: Codetext
Türöffnung | H2 Ebene 0 | 1113Tür0814282828 | m² | 0 | Zimmer- und Holzbauarbeiten | Türöffnung | 0 | 0 | NEW | 1113Wa 0812889013 | AllplanAttributes - Türanschlag: DIN L; Positionsnummer_Text: S68
Türöffnung | H2 Ebene 0 | 1113Tür0814282967 | m² | 0 | Zimmer- und Holzbauarbeiten | Türöffnung | 0 |  | NEW | AllplanAttributes - Türanschlag: DIN L
Türöffnung | H2 Ebene 0 | 1113Tür0814024279 | m² | 0 | Zimmer- und Holzbauarbeiten | Türöffnung | 0 |  | NEW | 1113Wa 0814024283 | AllplanAttributes - Türanschlag: DIN L
Türöffnung | H2 Ebene 0 | 1113Tür0814024280 | m² | -30 | Zimmer- und Holzbauarbeiten | Türöffnung | 0 |  | NEW | 1113Wa 0814024282 | AllplanAttributes - Türanschlag: DIN L
Türöffnung | H2 Ebene 0 | 1113Tür0814023467 | m² | 0 | Zimmer- und Holzbauarbeiten | Türöffnung | 0 | 0 | NEW | 1113Wa 0814023119 | AllplanAttributes - Türanschlag: -; Positionsnummer_Text: S68
Wandnische | H2 Ebene 0 | 1113Wni0814154054 | m² | 0 | Zimmer- und Holzbauarbeiten | Wandnische | 0 |  | NEW | 1113Wa 0812437354
Wandnische | H2 Ebene 0 | 1113Wni0814028854 | m² | 0 | Zimmer- und Holzbauarbeiten | Wandnische | 0 |  | NEW | 1113Wa 0812437354
Türöffnung | H2 Ebene 0 | 1113Tür0812435817 | m² |  | Zimmer- und Holzbauarbeiten | Türöffnung |  | 0 | NEW | 1113Wa 0812437344 | AllplanAttributes - Türanschlag: DIN L; Positionsnummer_Text: S68
Türöffnung | H2 Ebene 0 | 1113Tür0812845658 | m² | 0 | Zimmer- und Holzbauarbeiten | Türöffnung | 0 | 0 | NEW | 1113Wa 0812845633 | AllplanAttributes - Türanschlag: DIN L; Positionsnummer_Text: S68
Wandnische | H2 Ebene 0 | 1113Wni0814028860 | m² | 0 | Zimmer- und Holzbauarbeiten | Wandnische | 0 |  | NEW | 1113Wa 0812437655
Deckendurchbruch | H2 Ebene 0 |  |  |  |  |  |  |  | NEW | Pset_OpeningElementCommon - FireExit: no; AllplanAttributes - Object Layer Attributes #1, Gewerk: Betonarbeiten; Object Layer Attributes #1, Allright_Bauteil_ID: 1114Ddu0000015217; Object Layer Attributes #1, Abrechnungsart: m²; Object Layer Attributes #1, Objektname: Bodendurchbruch; Object Layer Attributes #1, Attributset-Objekt: OpeningElement
Deckendurchbruch | H2 Ebene 0 |  |  |  |  |  |  |  | NEW | Pset_OpeningElementCommon - FireExit: no; AllplanAttributes - Object Layer Attributes #1, Gewerk: Zimmer- und Holzbauarbeiten; Object Layer Attributes #1, Allright_Bauteil_ID: 1114Ddu0000003978; Object Layer Attributes #1, Abrechnungsart: m²; Object Layer Attributes #1, Objektname: Bodendurchbruch; Object Layer Attributes #1, Attributset-Objekt: OpeningElement
Deckendurchbruch | H2 Ebene 0 |  |  |  |  |  |  |  | NEW | Pset_OpeningElementCommon - FireExit: no; AllplanAttributes - Object Layer Attributes #1, Gewerk: Zimmer- und Holzbauarbeiten; Object Layer Attributes #1, Allright_Bauteil_ID: 1114Ddu0000003970; Object Layer Attributes #1, Abrechnungsart: m²; Object Layer Attributes #1, Objektname: Bodendurchbruch; Object Layer Attributes #1, Attributset-Objekt: OpeningElement
Deckendurchbruch | H2 Ebene 0 |  |  |  |  |  |  |  | NEW | Pset_OpeningElementCommon - FireExit: no; AllplanAttributes - Object Layer Attributes #1, Gewerk: Zimmer- und Holzbauarbeiten; Object Layer Attributes #1, Allright_Bauteil_ID: 1114Ddu0000003982; Object Layer Attributes #1, Abrechnungsart: m²; Object Layer Attributes #1, Objektname: Bodendurchbruch; Object Layer Attributes #1, Attributset-Objekt: OpeningElement
Deckendurchbruch | H2 Ebene 0 |  |  |  |  |  |  |  | NEW | Pset_OpeningElementCommon - FireExit: no; AllplanAttributes - Object Layer Attributes #1, Gewerk: Zimmer- und Holzbauarbeiten; Object Layer Attributes #1, Allright_Bauteil_ID: 1114Ddu0000003976; Object Layer Attributes #1, Abrechnungsart: m²; Object Layer Attributes #1, Objektname: Bodendurchbruch; Object Layer Attributes #1, Attributset-Objekt: OpeningElement
Deckendurchbruch | H2 Ebene 0 |  |  |  |  |  |  |  | NEW | Pset_OpeningElementCommon - FireExit: no; AllplanAttributes - Object Layer Attributes #1, Gewerk: Zimmer- und Holzbauarbeiten; Object Layer Attributes #1, Allright_Bauteil_ID: 1114Ddu0000003974; Object Layer Attributes #1, Abrechnungsart: m²; Object Layer Attributes #1, Objektname: Bodendurchbruch; Object Layer Attributes #1, Attributset-Objekt: OpeningElement
Deckendurchbruch | H2 Ebene 0 |  |  |  |  |  |  |  | NEW | Pset_OpeningElementCommon - FireExit: no; AllplanAttributes - Object Layer Attributes #1, Gewerk: Zimmer- und Holzbauarbeiten; Object Layer Attributes #1, Allright_Bauteil_ID: 1114Ddu0000003966; Object Layer Attributes #1, Abrechnungsart: m²; Object Layer Attributes #1, Objektname: Bodendurchbruch; Object Layer Attributes #1, Attributset-Objekt: OpeningElement
Deckendurchbruch | H2 Ebene 0 |  |  |  |  |  |  |  | NEW | Pset_OpeningElementCommon - FireExit: no; AllplanAttributes - Object Layer Attributes #1, Gewerk: Zimmer- und Holzbauarbeiten; Object Layer Attributes #1, Allright_Bauteil_ID: 1114Ddu0000003980; Object Layer Attributes #1, Abrechnungsart: m²; Object Layer Attributes #1, Objektname: Bodendurchbruch; Object Layer Attributes #1, Attributset-Objekt: OpeningElement
Deckendurchbruch | H2 Ebene 0 |  |  |  |  |  |  |  | NEW | Pset_OpeningElementCommon - FireExit: no; AllplanAttributes - Object Layer Attributes #1, Gewerk: Betonarbeiten; Object Layer Attributes #1, Allright_Bauteil_ID: 1114Ddu0000012458; Object Layer Attributes #1, Abrechnungsart: m²; Object Layer Attributes #1, Objektname: Bodendurchbruch; Object Layer Attributes #1, Attributset-Objekt: OpeningElement
Deckendurchbruch | H2 Ebene 0 |  |  |  |  |  |  |  | NEW | Pset_OpeningElementCommon - FireExit: no; AllplanAttributes - Object Layer Attributes #1, Gewerk: Betonarbeiten; Object Layer Attributes #1, Allright_Bauteil_ID: 1114Ddu0000012506; Object Layer Attributes #1, Abrechnungsart: m²; Object Layer Attributes #1, Objektname: Bodendurchbruch; Object Layer Attributes #1, Attributset-Objekt: OpeningElement
Deckendurchbruch | H2 Gründung |  |  |  |  |  |  |  | NEW | Pset_OpeningElementCommon - FireExit: no; AllplanAttributes - Object Layer Attributes #1, Gewerk: Betonarbeiten; Object Layer Attributes #1, Allright_Bauteil_ID: 1012Ddu0811367190; Object Layer Attributes #1, Abrechnungsart: m²; Object Layer Attributes #1, Objektname: Deckendurchbruch; Object Layer Attributes #1, Attributset-Objekt: OpeningElement
Deckendurchbruch | H2 Gründung |  |  |  |  |  |  |  | NEW | Pset_OpeningElementCommon - FireExit: no; AllplanAttributes - Object Layer Attributes #1, Gewerk: Betonarbeiten; Object Layer Attributes #1, Allright_Bauteil_ID: 1012Ddu0000001681; Object Layer Attributes #1, Abrechnungsart: m²; Object Layer Attributes #1, Objektname: Deckendurchbruch; Object Layer Attributes #1, Attributset-Objekt: OpeningElement

# IfcRailing (220)
Material: Holz
AllplanAttributes - Objektname: Handlauf; Material: Holz; Abrechnungsart: m³
Name | In | Allright_Bauteil_ID
 | H2 Ebene +2 | 1213ErE0813672193
 | H2 Ebene +2 | 1213ErE0813672198
 | H2 Ebene +2 | 1213ErE0813672203
 | H2 Ebene +2 | 1213ErE0813672208
 | H2 Ebene +2 | 1213ErE0813672213
 | H2 Ebene +2 | 1213ErE0813672218
 | H2 Ebene +2 | 1213ErE0813672223
 | H2 Ebene +2 | 1213ErE0813672228
 | H2 Ebene +2 | 1213ErE0813672233
 | H2 Ebene +2 | 1213ErE0813672238
 | H2 Ebene +2 | 1213ErE0813672243
 | H2 Ebene +2 | 1213ErE0813672248
 | H2 Ebene +2 | 1213ErE0813672253
 | H2 Ebene +2 | 1213ErE0813672258
 | H2 Ebene +2 | 1213ErE0813672263
 | H2 Ebene +2 | 1213ErE0813672268
 | H2 Ebene +2 | 1213ErE0813672273
 | H2 Ebene +2 | 1213ErE0813672278
 | H2 Ebene +2 | 1213ErE0813672283
 | H2 Ebene +2 | 1213ErE0813672288
 | H2 Ebene +2 | 1213ErE0813672293
 | H2 Ebene +2 | 1213ErE0813672298
 | H2 Ebene +2 | 1213ErE0813672303
 | H2 Ebene +2 | 1213ErE0813672308
 | H2 Ebene +2 | 1213ErE0813672313
 | H2 Ebene +2 | 1213ErE0813672318
 | H2 Ebene +2 | 1213ErE0813672323
 | H2 Ebene +2 | 1213ErE0813672328
 | H2 Ebene +2 | 1213ErE0813672333
 | H2 Ebene +2 | 1213ErE0813672338
 | H2 Ebene +2 | 1213ErE0813672343
 | H2 Ebene +2 | 1213ErE0813672348
 | H2 Ebene +2 | 1213ErE0813672353
 | H2 Ebene +2 | 1213ErE0813672358
 | H2 Ebene +2 | 1213ErE0813672363
 | H2 Ebene +2 | 1213ErE0813672368
 | H2 Ebene +2 | 1213ErE0813672373
 | H2 Ebene +2 | 1213ErE0813672378
 | H2 Ebene +2 | 1213ErE0813672384
 | H2 Ebene +2 | 1213ErE0813672389
 | H2 Ebene +2 | 1213ErE0813672394
 | H2 Ebene +2 | 1213ErE0813672399
 | H2 Ebene +2 | 1213ErE0813672404
 | H2 Ebene +2 | 1213ErE0813672409
 | H2 Ebene +2 | 1213ErE0813672414
 | H2 Ebene +2 | 1213ErE0813672419
 | H2 Ebene +2 | 1213ErE0813672424
 | H2 Ebene +2 | 1213ErE0813672429
 | H2 Ebene +2 | 1213ErE0813672434
 | H2 Ebene +2 | 1213ErE0813672439
 | H2 Ebene +2 | 1213ErE0813672444
 | H2 Ebene +2 | 1213ErE0813672449
 | H2 Ebene +2 | 1213ErE0813672454
 | H2 Ebene +2 | 1213ErE0813672459
 | H2 Ebene +2 | 1213ErE0813672464
 | H2 Ebene +2 | 1213ErE0813672469
 | H2 Ebene +2 | 1213ErE0813672474
 | H2 Ebene +2 | 1213ErE0813672479
 | H2 Ebene +2 | 1213ErE0813672484
 | H2 Ebene +2 | 1213ErE0813672489
 | H2 Ebene +2 | 1213ErE0813672494
 | H2 Ebene +2 | 1213ErE0813672504
 | H2 Ebene +2 | 1213ErE0813672509
 | H2 Ebene +2 | 1213ErE0813672519
 | H2 Ebene +2 | 1213ErE0813672524
 | H2 Ebene +2 | 1213ErE0813672529
 | H2 Ebene +2 | 1213ErE0813672534
 | H2 Ebene +2 | 1213ErE0813672539
 | H2 Ebene +2 | 1213ErE0813672544
 | H2 Ebene +2 | 1213ErE0813672549
 | H2 Ebene +2 | 1213ErE0813672554
 | H2 Ebene +2 | 1213ErE0813672559
 | H2 Ebene +2 | 1213ErE0813672379
 | H2 Ebene +2 | 1213ErE0813672514
 | H2 Ebene +2 | 1213ErE0813672499
 | H2 Ebene +2 | 1213ErE0813730184
 | H2 Ebene +1 | 1163ErE0814777733
 | H2 Ebene +1 | 1163ErE0814777734
 | H2 Ebene +1 | 1163ErE0814777735
 | H2 Ebene +1 | 1163ErE0814777736
 | H2 Ebene +1 | 1163ErE0814763159
 | H2 Ebene +1 | 1163ErE0814763164
 | H2 Ebene +1 | 1163ErE0814763169
 | H2 Ebene +1 | 1163ErE0814777737
 | H2 Ebene +1 | 1163ErE0814777738
 | H2 Ebene +1 | 1163ErE0814777740
 | H2 Ebene +1 | 1163ErE0814777741
 | H2 Ebene +1 | 1163ErE0814777742
 | H2 Ebene +1 | 1163ErE0814777743
 | H2 Ebene +1 | 1163ErE0814777744
 | H2 Ebene +1 | 1163ErE0814777755
 | H2 Ebene +1 | 1163ErE0814777756
 | H2 Ebene +1 | 1163ErE0814777762
 | H2 Ebene +1 | 1163ErE0814777763
 | H2 Ebene +1 | 1163ErE0814763217
 | H2 Ebene +1 | 1163ErE0814763222
 | H2 Ebene +1 | 1163ErE0814777764
 | H2 Ebene +1 | 1163ErE0814777765
 | H2 Ebene +1 | 1163ErE0814777766
 | H2 Ebene +1 | 1163ErE0814777767
 | H2 Ebene +1 | 1163ErE0814777768
 | H2 Ebene +1 | 1163ErE0814777769
 | H2 Ebene +1 | 1163ErE0814777770
 | H2 Ebene +1 | 1163ErE0814777771
 | H2 Ebene +1 | 1163ErE0814777772
 | H2 Ebene +1 | 1163ErE0814777773
 | H2 Ebene +1 | 1163ErE0814777774
 | H2 Ebene +1 | 1163ErE0814777775
 | H2 Ebene +1 | 1163ErE0814777776
 | H2 Ebene +1 | 1163ErE0814777777
 | H2 Ebene +1 | 1163ErE0814763283
 | H2 Ebene +1 | 1163ErE0814777789
 | H2 Ebene +1 | 1163ErE0814777790
 | H2 Ebene +1 | 1163ErE0814777791
 | H2 Ebene +1 | 1163ErE0814777792
 | H2 Ebene +1 | 1163ErE0814777793
 | H2 Ebene +1 | 1163ErE0814777794
 | H2 Ebene +1 | 1163ErE0814777795
 | H2 Ebene +1 | 1163ErE0814777796
 | H2 Ebene +1 | 1163ErE0814777797
 | H2 Ebene +1 | 1163ErE0814777778
 | H2 Ebene +1 | 1163ErE0814777779
 | H2 Ebene +1 | 1163ErE0814777780
 | H2 Ebene +1 | 1163ErE0814777781
 | H2 Ebene +1 | 1163ErE0814763383
 | H2 Ebene +1 | 1163ErE0814763388
 | H2 Ebene +1 | 1163ErE0814763393
 | H2 Ebene +1 | 1163ErE0814763398
 | H2 Ebene +1 | 1163ErE0814763403
 | H2 Ebene +1 | 1163ErE0814777798
 | H2 Ebene +1 | 1163ErE0814777799
 | H2 Ebene +1 | 1163ErE0814777783
 | H2 Ebene +1 | 1163ErE0814777784
 | H2 Ebene +1 | 1163ErE0814763650
 | H2 Ebene +1 | 1163ErE0814763655
 | H2 Ebene +1 | 1163ErE0814763660
 | H2 Ebene +1 | 1163ErE0814763665
 | H2 Ebene +1 | 1163ErE0814763670
 | H2 Ebene +1 | 1163ErE0814763675
 | H2 Ebene +1 | 1163ErE0814777739
 | H2 Ebene +1 | 1163ErE0814777749
 | H2 Ebene +1 | 1163ErE0814777761
 | H2 Ebene +1 | 1163ErE0814777817
 | H2 Ebene +1 | 1163ErE0814777808
 | H2 Ebene +1 | 1163ErE0814777818
 | H2 Ebene +1 | 1163ErE0814777819
 | H2 Ebene +1 | 1163ErE0814777782
 | H2 Ebene +1 | 1163ErE0814777754
 | H2 Ebene 0 | 1113ErE0814016042
 | H2 Ebene 0 | 1113ErE0814016049
 | H2 Ebene 0 | 1113ErE0814016055
 | H2 Ebene 0 | 1113ErE0814272334
 | H2 Ebene 0 | 1113ErE0814016073
 | H2 Ebene 0 | 1113ErE0814272341
 | H2 Ebene 0 | 1113ErE0814272335
 | H2 Ebene 0 | 1113ErE0814272336
 | H2 Ebene 0 | 1113ErE0814272337
 | H2 Ebene 0 | 1113ErE0814272338
 | H2 Ebene 0 | 1113ErE0814016163
 | H2 Ebene 0 | 1113ErE0814016199
 | H2 Ebene 0 | 1113ErE0814016205
 | H2 Ebene 0 | 1113ErE0814016235
 | H2 Ebene 0 | 1113ErE0814272344
 | H2 Ebene 0 | 1113ErE0814272345
 | H2 Ebene 0 | 1113ErE0814272356
 | H2 Ebene 0 | 1113ErE0814272357
 | H2 Ebene 0 | 1113ErE0814272358
 | H2 Ebene 0 | 1113ErE0814272359
 | H2 Ebene 0 | 1113ErE0814016373
 | H2 Ebene 0 | 1113ErE0814272353
 | H2 Ebene 0 | 1113ErE0814272354
 | H2 Ebene 0 | 1113ErE0814272371
 | H2 Ebene 0 | 1113ErE0814272372
 | H2 Ebene 0 | 1113ErE0814272373
 | H2 Ebene 0 | 1113ErE0814272374
 | H2 Ebene 0 | 1113ErE0814272375
 | H2 Ebene 0 | 1113ErE0814272376
 | H2 Ebene 0 | 1113ErE0814272377
 | H2 Ebene 0 | 1113ErE0814272378
 | H2 Ebene 0 | 1113ErE0814016529
 | H2 Ebene 0 | 1113ErE0814272379
 | H2 Ebene 0 | 1113ErE0814272380
 | H2 Ebene 0 | 1113ErE0814272381
 | H2 Ebene 0 | 1113ErE0814272382
 | H2 Ebene 0 | 1113ErE0814272383
 | H2 Ebene 0 | 1113ErE0814272384
 | H2 Ebene 0 | 1113ErE0814272385
 | H2 Ebene 0 | 1113ErE0814272386
 | H2 Ebene 0 | 1113ErE0814272387
 | H2 Ebene 0 | 1113ErE0814272388
 | H2 Ebene 0 | 1113ErE0814016625
 | H2 Ebene 0 | 1113ErE0814272346
 | H2 Ebene 0 | 1113ErE0814016367
 | H2 Ebene 0 | 1113ErE0814272339
 | H2 Ebene 0 | 1113ErE0814272360
 | H2 Ebene 0 | 1113ErE0814272347
 | H2 Ebene 0 | 1113ErE0814272389
 | H2 Ebene 0 | 1113ErE0814272355
 | H2 Ebene 0 | 1113ErE0814272390
 | H2 Ebene 0 | 1113ErE0814272342
 | H2 Ebene 0 | 1113ErE0814272343
 | H2 Ebene 0 | 1113ErE0814272340
 | H2 Ebene 0 | 1113ErE0814272348
 | H2 Ebene 0 | 1113ErE0814272361
 | H2 Ebene 0 | 1113ErE0814272362
 | H2 Ebene 0 | 1113ErE0814272391
 | H2 Ebene 0 | 1113ErE0814268062
 | H2 Ebene 0 | 1113ErE0814272392
 | H2 Ebene 0 | 1113ErE0814272301
 | H2 Ebene 0 | 1113ErE0814272307
 | H2 Ebene 0 | 1113ErE0814272312
 | H2 Ebene 0 | 1113ErE0814272317
 | H2 Ebene 0 | 1113ErE0814272349
 | H2 Ebene 0 | 1113ErE0814272350
 | H2 Ebene 0 | 1113ErE0814272351
 | H2 Ebene 0 | 1113ErE0814272352
 | H2 Ebene 0 | 1113ErE0814016487
 | H2 Ebene 0 | 1113ErE0814016565
 | H2 Ebene 0 | 1113ErE0814273371
 | H2 Ebene 0 | 1113ErE0814273401

# IfcRoof (8)
In: H2 Ebene +4/ Dachebene
Material: DA04
AllplanAttributes - 2D Interaktion: yes; Objektname: Dachhautschicht; Material: DA04; Tragendes Bauteil: no; Projektionsfläche: 0; Attributset-Objekt: Roof; Abrechnungsart: m²
Pset_RoofCommon - Status: NEW; IsExternal: yes; ThermalTransmittance: 0 W/K/m2
Name | Allright_Bauteil_ID
 | 1408ErE0000017001
 | 1408ErE0000017002
 | 1408ErE0000016997
 | 1408ErE0000016998
 | 1408ErE0000016999
 | 1408ErE0000017000
 | 1408ErE0000017004
 | 1408ErE0000017003

# IfcSlab (70)
AllplanAttributes - 2D Interaktion: yes; Abrechnungsart: m²
Pset_SlabCommon - Status: NEW; LoadBearing: yes
Name | In | PredefinedType | Material = AllplanAttributes, Material | Gewerk | Allright_Bauteil_ID | Objektname | ProductionYear | IsExternal | FireRating | ThermalTransmittance (W/K/m2) | Combustible = Compartmentation
 | H2 Ebene +3 | FLOOR | STB | Betonarbeiten | 1264De 0000000451 | Decke | 0 | no | REI 90-A1 | 0 | no
 | H2 Ebene +2 | FLOOR | STB | Betonarbeiten | 1214De 0000006986 | Decke | 0 | no | REI 90-A1 | 0 | no
 | H2 Ebene +2 | FLOOR | Stb | Betonarbeiten | 1214De 0000007459 | Decke | 0 | no | - | 0 | no | AllplanAttributes - Ortscode_Geschoßbezeichnung: E02; OKFF: 7.5
 | H2 Ebene +2 | FLOOR | Stb | Betonarbeiten | 1214De 0000005717 | Decke | 0 | no | - | 0 | no | AllplanAttributes - Ortscode_Geschoßbezeichnung: E02; OKFF: 7.5
 | H2 Ebene +2 | FLOOR | Stb | Betonarbeiten | 1214De 0000005720 | Decke | 0 | no | - | 0 | no | AllplanAttributes - OKFF: 7.5
 | H2 Ebene +2 | FLOOR | Stb | Betonarbeiten | 1214De 0000005715 | Decke | 0 | no | - | 0 | no | AllplanAttributes - OKFF: 7.5
 | H2 Ebene +2 | FLOOR | Stb | Betonarbeiten | 1214De 0000005727 | Decke | 0 | no | - | 0 | no | AllplanAttributes - Ortscode_Geschoßbezeichnung: E02; OKFF: 7.5
 | H2 Ebene +2 | FLOOR | Stb | Betonarbeiten | 1214De 0813473900 | Decke | 0 | no | REI 90-A1 | 0 | no
 | H2 Ebene +2 | FLOOR | H | Zimmer- und Holzbauarbeiten | 1214De 0813471515 | Decke | 0 | no | - | 0 | no
 | H2 Ebene +2 | FLOOR | Stb | Betonarbeiten | 1214De 0813473054 | Decke | 0 | no | REI 90-A1 | 0 | no
 | H2 Ebene +2 | FLOOR | STB | Betonarbeiten | 1214De 0000002647 | Decke | 0 | no | REI 90-A1 | 0 | no
 | H2 Ebene +2 | FLOOR | STB | Betonarbeiten | 1214De 0000003525 | Decke | 0 | no | REI 90-A1 | 0 | no
 | H2 Ebene +2 | FLOOR | H | Zimmer- und Holzbauarbeiten | 1214De 0000002649 | Decke | 0 | no | - | 0 | no
 | H2 Ebene +2 | FLOOR | H | Zimmer- und Holzbauarbeiten | 1214De 0000002645 | Decke | 0 | no | - | 0 | no
 | H2 Ebene +2 | FLOOR | Stb | Betonarbeiten | 1214De 0000005711 | Decke | 0 | no | - | 0 | no | AllplanAttributes - Ortscode_Geschoßbezeichnung: E02; OKFF: 7.5
 | H2 Ebene +2 | FLOOR | Stb | Betonarbeiten | 1214De 0000005729 | Decke | 0 | no | - | 0 | no | AllplanAttributes - Ortscode_Geschoßbezeichnung: E02; OKFF: 7.5
 | H2 Ebene +2 | FLOOR | H | Zimmer- und Holzbauarbeiten | 1214De 0000007916 | Decke | 0 | no | - | 0 | no
 | H2 Ebene +2 | FLOOR | H | Zimmer- und Holzbauarbeiten | 1214De 0813471510 | Decke | 0 | no | - | 0 | no
 | H2 Ebene +2 | FLOOR | STB | Betonarbeiten | 1214De 0000004287 | Decke | 0 | no | REI 90-A1 | 0 | no
 | H2 Ebene +2 | FLOOR | Stb | Betonarbeiten | 1214De 0000004627 | Decke | 0 | no | REI 90-A1 | 0 | no
 | H2 Ebene +1 | FLOOR | STB | Betonarbeiten | 1164De 0000005015 | Decke | 0 | no | 0 | 0.9 | no | AllplanAttributes - Sicherheitsklasse: -; Sonnenschutztyp: Movable; g-Wert: 0,51; Pset_SlabCommon - AcousticRating: 32
 | H2 Ebene +1 | FLOOR | STB | Betonarbeiten | 1164De 0000005146 | Decke | 0 | no | 0 | 0.9 | no | AllplanAttributes - Sicherheitsklasse: -; Sonnenschutztyp: Movable; g-Wert: 0,51; Pset_SlabCommon - AcousticRating: 32
 | H2 Ebene +1 | FLOOR | Stb | Betonarbeiten | 1164De 0000009911 | Decke | 0 | no | - | 0 | no | AllplanAttributes - OKFF: 7.5
 | H2 Ebene +1 | FLOOR | Stb | Betonarbeiten | 1164De 0000009879 | Decke | 0 | no | - | 0 | no | AllplanAttributes - Ortscode_Geschoßbezeichnung: E01; OKFF: 3.75; Positionsnummer_Text: U100
 | H2 Ebene +1 | FLOOR | Stb | Betonarbeiten | 1164De 0000009877 | Decke | 0 | no | - | 0 | no | AllplanAttributes - Ortscode_Geschoßbezeichnung: E01; OKFF: 3.75; Positionsnummer_Text: U100
 | H2 Ebene +1 | FLOOR | STB | Betonarbeiten | 1164De 0000004988 | Decke | 0 | no | 0 | 0.9 | no | AllplanAttributes - Sicherheitsklasse: -; Sonnenschutztyp: Movable; g-Wert: 0,51; Pset_SlabCommon - AcousticRating: 32
 | H2 Ebene +1 | FLOOR | Stb | Betonarbeiten | 1164De 0000004135 | Decke | 0 | no | 0 | 0.9 | no | AllplanAttributes - Sicherheitsklasse: -; Sonnenschutztyp: Movable; g-Wert: 0,51; Pset_SlabCommon - AcousticRating: 32
 | H2 Ebene +1 | FLOOR | Stb | Betonarbeiten | 1164De 0000004119 | Decke | 0 | no | 0 | 0.9 | no | AllplanAttributes - Sicherheitsklasse: -; Sonnenschutztyp: Movable; g-Wert: 0,51; Pset_SlabCommon - AcousticRating: 32
 | H2 Ebene +1 | FLOOR | H | Zimmer- und Holzbauarbeiten | 1164De 0000004117 | Decke | 0 | no | 0 | 0.9 | no | AllplanAttributes - Sicherheitsklasse: -; Sonnenschutztyp: Movable; g-Wert: 0,51; Pset_SlabCommon - AcousticRating: 32
 | H2 Ebene +1 | FLOOR | H | Zimmer- und Holzbauarbeiten | 1164De 0000004115 | Decke | 0 | no | 0 | 0.9 | no | AllplanAttributes - Sicherheitsklasse: -; Sonnenschutztyp: Movable; g-Wert: 0,51; Pset_SlabCommon - AcousticRating: 32
 | H2 Ebene +1 | FLOOR | Stb | Betonarbeiten | 1164De 0000009883 | Decke | 0 | no | - | 0 | no | AllplanAttributes - Ortscode_Geschoßbezeichnung: E01; OKFF: 3.75; Positionsnummer_Text: U100
 | H2 Ebene +1 | FLOOR | Stb | Betonarbeiten | 1164De 0000009881 | Decke | 0 | no | - | 0 | no | AllplanAttributes - Ortscode_Geschoßbezeichnung: E01; OKFF: 3.75; Positionsnummer_Text: U100
 | H2 Ebene +1 | FLOOR | Stb | Betonarbeiten | 1164De 0000009913 | Decke | 0 | no | - | 0 | no | AllplanAttributes - Ortscode_Geschoßbezeichnung: E02; OKFF: 7.5
 | H2 Ebene +1 | FLOOR | Stb | Betonarbeiten | 1164De 0000009887 | Decke | 0 | no | - | 0 | no | AllplanAttributes - Ortscode_Geschoßbezeichnung: E01; OKFF: 3.75; Positionsnummer_Text: U100
 | H2 Ebene +1 | FLOOR | Stb | Betonarbeiten | 1164De 0000009885 | Decke | 0 | no | - | 0 | no | AllplanAttributes - Ortscode_Geschoßbezeichnung: E01; OKFF: 3.75; Positionsnummer_Text: U100
 | H2 Ebene +1 | FLOOR | Stb | Betonarbeiten | 1164De 0000009915 | Decke | 0 | no | - | 0 | no | AllplanAttributes - OKFF: 7.5
 | H2 Ebene +1 | FLOOR | Stb | Betonarbeiten | 1164De 0000009889 | Decke | 0 | no | - | 0 | no | AllplanAttributes - Ortscode_Geschoßbezeichnung: E01; OKFF: 3.75; Positionsnummer_Text: U100
 | H2 Ebene +1 | FLOOR | Stb | Betonarbeiten | 1164De 0000009891 | Decke | 0 | no | - | 0 | no | AllplanAttributes - Ortscode_Geschoßbezeichnung: E01; OKFF: 3.75; Positionsnummer_Text: U100
 | H2 Ebene +1 | FLOOR | STB | Betonarbeiten | 1164De 0000004139 | Decke | 0 | no | 0 | 0.9 | no | AllplanAttributes - Sicherheitsklasse: -; Sonnenschutztyp: Movable; g-Wert: 0,51; Pset_SlabCommon - AcousticRating: 32
 | H2 Ebene +1 | FLOOR | STB | Betonarbeiten | 1164De 0000005385 | Decke | 0 | no | 0 | 0.9 | no | AllplanAttributes - Sicherheitsklasse: -; Sonnenschutztyp: Movable; g-Wert: 0,51; Pset_SlabCommon - AcousticRating: 32
 | H2 Ebene +1 | FLOOR | Stb | Betonarbeiten | 1164De 0000007241 | Decke | 0 | no | 0 | 0.9 | no | AllplanAttributes - Sicherheitsklasse: -; Sonnenschutztyp: Movable; g-Wert: 0,51; Pset_SlabCommon - AcousticRating: 32
 | H2 Ebene +1 | FLOOR | H | Zimmer- und Holzbauarbeiten | 1164De 0000013036 | Decke | 0 | no | 0 | 0.9 | no | AllplanAttributes - Sicherheitsklasse: -; Sonnenschutztyp: Movable; g-Wert: 0,51; Pset_SlabCommon - AcousticRating: 35
 | H2 Ebene +1 | FLOOR | Stb | Betonarbeiten | 1164De 0000009875 | Decke | 0 | no | - | 0 | no | AllplanAttributes - Ortscode_Geschoßbezeichnung: E01; OKFF: 3.75; Positionsnummer_Text: U100
 | H2 Ebene +1 | FLOOR | STB | Betonarbeiten | 1164De 0000005465 | Decke | 0 | no | 0 | 0.9 | no | AllplanAttributes - Sicherheitsklasse: -; Sonnenschutztyp: Movable; g-Wert: 0,51; Pset_SlabCommon - AcousticRating: 32
 | H2 Ebene 0 | FLOOR | STB | Betonarbeiten | 1114De 0000005155 | Decke | 0 | no | REI 90-A1 | 0 | no
 | H2 Ebene 0 | FLOOR | STB | Betonarbeiten | 1114De 0000005274 | Decke | 0 | no | REI 90-A1 | 0 | no
 | H2 Ebene 0 | FLOOR | Stb | Betonarbeiten | 1114De 0000009171 | Decke | 0 | no | - | 0 | no | AllplanAttributes - Ortscode_Geschoßbezeichnung: E00; OKFF: 0; Positionsnummer_Text: S68
 | H2 Ebene 0 | FLOOR | Stb | Betonarbeiten | 1114De 0000009161 | Decke | 0 | no | - | 0 | no | AllplanAttributes - Ortscode_Geschoßbezeichnung: E00; OKFF: 0; Positionsnummer_Text: S68
 | H2 Ebene 0 | FLOOR | Stb | Betonarbeiten | 1114De 0000010294 | Decke | 0 | no | - | 0 | no | AllplanAttributes - OKFF: 0; Positionsnummer_Text: S68
 | H2 Ebene 0 | FLOOR | H | Zimmer- und Holzbauarbeiten | 1114De 0000014180 | Decke | 0 | no | - | 0 | no
 | H2 Ebene 0 | FLOOR | Stb | Betonarbeiten | 1114De 0000004013 | Decke | 0 | no | REI 90-A1 | 0 | no
 | H2 Ebene 0 | FLOOR | STB | Betonarbeiten | 1114De 0000005091 | Decke | 0 | no | REI 90-A1 | 0 | no
 | H2 Ebene 0 | FLOOR | STB | Betonarbeiten | 1114De 0000005335 | Decke | 0 | no | REI 90-A1 | 0 | no
 | H2 Ebene 0 | FLOOR | Stb | Betonarbeiten | 1114De 0000004017 | Decke | 0 | no | REI 90-A1 | 0 | no
 | H2 Ebene 0 | FLOOR | H | Zimmer- und Holzbauarbeiten | 1114De 0000003995 | Decke | 0 | no | - | 0 | no
 | H2 Ebene 0 | FLOOR | Stb | Betonarbeiten | 1114De 0000010291 | Decke | 0 | no | - | 0 | no | AllplanAttributes - OKFF: 0; Positionsnummer_Text: S68
 | H2 Ebene 0 | FLOOR | Stb | Betonarbeiten | 1114De 0000009175 | Decke | 0 | no | - | 0 | no | AllplanAttributes - OKFF: 0; Positionsnummer_Text: S68
 | H2 Ebene 0 | FLOOR | Stb | Betonarbeiten | 1114De 0000009159 | Decke | 0 | no | - | 0 | no | AllplanAttributes - Ortscode_Geschoßbezeichnung: E00; OKFF: 0; Positionsnummer_Text: S68
 | H2 Ebene 0 | FLOOR | Stb | Betonarbeiten | 1114De 0000009163 | Decke | 0 | no | - | 0 | no | AllplanAttributes - Ortscode_Geschoßbezeichnung: E00; OKFF: 0; Positionsnummer_Text: S68
 | H2 Ebene 0 | FLOOR | Stb | Betonarbeiten | 1114De 0000009173 | Decke | 0 | no | - | 0 | no | AllplanAttributes - Ortscode_Geschoßbezeichnung: E00; OKFF: 0; Positionsnummer_Text: S68
 | H2 Ebene 0 | FLOOR | Stb | Betonarbeiten | 1114De 0000009169 | Decke | 0 | no | - | 0 | no | AllplanAttributes - Ortscode_Geschoßbezeichnung: E00; OKFF: 0; Positionsnummer_Text: S68
 | H2 Ebene 0 | FLOOR | Stb | Betonarbeiten | 1114De 0000009167 | Decke | 0 | no | - | 0 | no | AllplanAttributes - Ortscode_Geschoßbezeichnung: E00; OKFF: 0; Positionsnummer_Text: S68
 | H2 Ebene 0 | FLOOR | Stb | Betonarbeiten | 1114De 0000009157 | Decke | 0 | no | - | 0 | no | AllplanAttributes - Ortscode_Geschoßbezeichnung: E00; OKFF: 0; Positionsnummer_Text: S68
 | H2 Ebene 0 | FLOOR | H | Zimmer- und Holzbauarbeiten | 1114De 0000004009 | Decke | 0 | no | - | 0 | no
 | H2 Ebene 0 | FLOOR | Stb. | Betonarbeiten | 1114De 0000007544 | Decke | 0 | no | REI 90-A1 | 0 | no
 | H2 Ebene 0 | FLOOR | Stb | Betonarbeiten | 1114De 0000004011 | Decke | 0 | no | REI 90-A1 | 0 | no
 | H2 Ebene 0 | FLOOR | STB | Betonarbeiten | 1114De 0000005640 | Decke | 0 | no | REI 90-A1 | 0 | no
 | H2 Ebene 0 | FLOOR | Stb | Betonarbeiten | 1114De 0000009165 | Decke | 0 | no | - | 0 | no | AllplanAttributes - Ortscode_Geschoßbezeichnung: E00; OKFF: 0; Positionsnummer_Text: S68
 | H2 Ebene 0 | FLOOR | STB | Betonarbeiten | 1114De 0000005591 | Decke | 0 | no | REI 90-A1 | 0 | no
 | H2 Gründung | BASESLAB | WUB | Betonarbeiten | 1012PFu0000001592 | Bodenplatte |  | yes | AllplanAttributes - ash D_Detailverweis: BP; ash D_Plannummer: D1860

# IfcWall (6826)
Name | In | Material | Allright_Bauteil_ID | 2D Interaktion | Codetext | Abrechnungsart | Gewerk | Objektname | Bezeichnung | AllplanAttributes, Material | Typ = SurfaceSpreadOfFlame | Brandschutzklasse | OKFF | P_ID | Status | LoadBearing | IsExternal | FireRating | ThermalTransmittance (W/K/m2) | Combustible | AcousticRating | Compartmentation | Reference
 | H2 Ebene +4/ Dachebene | WI-STB | 1406Wa 0000005301 | yes | Codetext | m² | Betonarbeiten | Wand | Innenwand 1-Schalig | WI-STB | 0 | A | 14.5 | 1263HWa0812610107 | NEW | yes | no | REI 60-A1 - A2,s1-d0 / A1 | 0 | no | 0 | no | Codetext | AllplanAttributes - Ortscode_Geschoßbezeichnung: E04; ash D_Detailverweis: DT 3; ash D_Plannummer: D1615
 | H2 Ebene +4/ Dachebene | WI-LB | 1406Wa 0000005322 | yes | Codetext | m² | Trockenbauarbeiten | Wand | Innenwand 1-Schalig | WI-LB | 0 | A | 14.5 | 1263HWa0812546813 | NEW | no | no | REI 60-A1 - A2,s1-d0 / A1 | 0 | no | 0 | no | Codetext | AllplanAttributes - Ortscode_Geschoßbezeichnung: E04; W_Deckenanschluss: Gleitender Deckenanschluss Fall 01
 | H2 Ebene +4/ Dachebene | WI-LB | 1406Wa 0000005305 | yes | Codetext | m² | Trockenbauarbeiten | Wand | Innenwand 1-Schalig | WI-LB | 0 | A | 14.5 | 1263HWa0812545245 | NEW | no | no | REI 60-A1 - A2,s1-d0 / A1 | 0 | no | 0 | no | Codetext | AllplanAttributes - Ortscode_Geschoßbezeichnung: E04; W_Deckenanschluss: Gleitender Deckenanschluss Fall 01; ash_W_Trockenbau_Qualitäten: 1b
 | H2 Ebene +4/ Dachebene | WI-LB | 1406Wa 0000005312 | yes | Codetext | m² | Trockenbauarbeiten | Wand | Innenwand 1-Schalig | WI-LB | 0 | A | 14.5 | 1263HWa0812545245 | NEW | no | no | REI 60-A1 - A2,s1-d0 / A1 | 0 | no | 0 | no | Codetext | AllplanAttributes - Ortscode_Geschoßbezeichnung: E04; W_Deckenanschluss: Gleitender Deckenanschluss Fall 01; ash_W_Trockenbau_Qualitäten: 1b
 | H2 Ebene +4/ Dachebene | WI-HW 60 | 1406Wa 0000005266 | yes | Codetext | m² | Trockenbauarbeiten | Wand | Innenwand 1-Schalig | WI-HW 60 | 0 | A | 14.5 | 1263HWa0812546596 | NEW | no | no | REI-M 60-D,s2,d0 + A1 | 0 | no | 0 | no | Codetext | AllplanAttributes - ash D_Detailverweis: DT 8; ash D_Plannummer: D1613
 | H2 Ebene +4/ Dachebene | WI-HW 60 | 1406Wa 0000005270 | yes | Codetext | m² | Trockenbauarbeiten | Wand | Innenwand 1-Schalig | WI-HW 60 | 0 | A | 14.5 | 1263HWa0812844429 | NEW | yes | no | REI 60-A1 - A2,s1-d0 / A1 | 0 | no |  | no | Codetext | AllplanAttributes - ash D_Detailverweis: J2; ash D_Plannummer: D1651
 | H2 Ebene +4/ Dachebene | WI-HW 60 | 1406Wa 0000005375 | yes | Codetext | m² | Trockenbauarbeiten | Wand | Innenwand 1-Schalig | WI-HW 60 | 0 | A | 14.5 | 1263HWa0812546501 | NEW | yes | no | REI 60-A1 - A2,s1-d0 / A1 | 0 | no |  | no | Codetext
 | H2 Ebene +4/ Dachebene | WI-HW 60 | 1406Wa 0000005359 | yes | Codetext | m² | Trockenbauarbeiten | Wand | Innenwand 1-Schalig | WI-HW 60 | 0 | A | 14.5 | 1263HWa0812915121 | NEW | yes | no | REI 60-A1 - A2,s1-d0 / A1 | 0 | no | 47 | no | Codetext
 | H2 Ebene +4/ Dachebene | WI-LB | 1406Wa 0000005274 | yes | Codetext | m² | Trockenbauarbeiten | Wand | Innenwand 1-Schalig | WI-LB | 0 | A | 14.5 | 1263HWa0812595068 | NEW | no | no | REI 60-A1 - A2,s1-d0 / A1 | 0 | no | 47 | no | Codetext | AllplanAttributes - W_Deckenanschluss: Gleitender Deckenanschluss Fall 01; ash_W_Trockenbau_Qualitäten: 1b
 | H2 Ebene +4/ Dachebene | WI-LB | 1406Wa 0000005286 | yes | Codetext | m² | Trockenbauarbeiten | Wand | Innenwand 1-Schalig | WI-LB | 0 | A | 14.5 | 1263HWa0812595656 | NEW | no | no | 0 | 0 | no | 0 | no | Codetext | AllplanAttributes - W_Deckenanschluss: Gleitender Deckenanschluss Fall 01; ash_W_Trockenbau_Qualitäten: 10a
 | H2 Ebene +4/ Dachebene | WI-LB | 1406Wa 0000005368 | yes | Codetext | m² | Trockenbauarbeiten | Wand | Innenwand 1-Schalig | WI-LB | 0 | A | 14.5 | 1263HWa0812595716 | NEW | no | no | 0 | 0 | no | 0 | no | Codetext | AllplanAttributes - W_Deckenanschluss: Gleitender Deckenanschluss Fall 01; ash_W_Trockenbau_Qualitäten: 10a
 | H2 Ebene +4/ Dachebene | Installationsraum | 1406Wa 0000005371 | yes | Codetext | m² | Trockenbauarbeiten | Wand | Installationswand | Installationsraum | 0 | A | 14.5 | 1263HWa0812596018 | NEW | no | no | 0 | 0 | no | 0 | no | Codetext | AllplanAttributes - W_Deckenanschluss: Gleitender Deckenanschluss Fall 01
 | H2 Ebene +4/ Dachebene | WI-VS | 1406Wa 0000005281 | yes | Codetext | m² | Trockenbauarbeiten | Wand | Installationswand | WI-VS | 0 | A | 14.5 | 1263HWa0812596018 | NEW | no | no | 0 | 0 | no | 0 | no | Codetext | AllplanAttributes - W_Deckenanschluss: Gleitender Deckenanschluss Fall 01; ash_W_Trockenbau_Qualitäten: 3
 | H2 Ebene +4/ Dachebene | Installationsraum | 1406Wa 0000005290 | yes | Codetext | m² | Trockenbauarbeiten | Wand | Installationswand | Installationsraum | 0 | A | 14.5 | 1263HWa0812596019 | NEW | no | no | 0 | 0 | no | 0 | no | Codetext | AllplanAttributes - W_Deckenanschluss: Gleitender Deckenanschluss Fall 01
 | H2 Ebene +4/ Dachebene | WI-VS | 1406Wa 0000005278 | yes | Codetext | m² | Trockenbauarbeiten | Wand | Installationswand | WI-VS | 0 | A | 14.5 | 1263HWa0812596019 | NEW | no | no | 0 | 0 | no | 0 | no | Codetext | AllplanAttributes - W_Deckenanschluss: Gleitender Deckenanschluss Fall 01; ash_W_Trockenbau_Qualitäten: 3
 | H2 Ebene +4/ Dachebene | WI-LB | 1406Wa 0000005363 | yes | Codetext | m² | Trockenbauarbeiten | Wand | Innenwand 1-Schalig | WI-LB | 0 | A | 14.5 | 1263HWa0812546497 | NEW | no | no | REI-M 60-A1 | 0 | no | 47 | no | Codetext | AllplanAttributes - W_Deckenanschluss: Gleitender Deckenanschluss Fall 01; ash_W_Trockenbau_Qualitäten: 1b
 | H2 Ebene +4/ Dachebene | WI-STB | 1406Wa 0000005381 | yes | Codetext | m² | Betonarbeiten | Wand | Innenwand 1-Schalig | WI-STB | 0 | A | 14.5 | 1263HWa0812546824 | NEW | yes | no | REI-M 60-A1 | 0 | no | 47 | no | Codetext | AllplanAttributes - ash D_Detailverweis: DT 3; ash D_Plannummer: D1615; Text1: SB3
 | H2 Ebene +4/ Dachebene | WI-LB | 1406Wa 0000005350 | yes | Codetext | m² | Trockenbauarbeiten | Wand | Innenwand 1-Schalig | WI-LB | 0 | A | 14.5 | 1263HWa0812544238 | NEW | no | no | REI 60-A1 - D,s2-d0 +A1 | 0 | no | 0 | no | Codetext | AllplanAttributes - ash_W_Trockenbau_Qualitäten: 9
 | H2 Ebene +4/ Dachebene | WI-STB | 1406Wa 0000005329 | yes | Codetext | m² | Betonarbeiten | Wand | Innenwand 1-Schalig | WI-STB | 0 | A | 14.5 | 1263HWa0812544238 | NEW | yes | no | REI 60-A1 - A2,s1-d0 / A1 | 0 | no | 0 | no | Codetext | AllplanAttributes - ash D_Detailverweis: DT 3; ash D_Plannummer: D1615; Text1: SB3
 | H2 Ebene +4/ Dachebene | WI-STB | 1406Wa 0000005297 | yes | Codetext | m² | Betonarbeiten | Wand | Innenwand 1-Schalig | WI-STB | 0 | A | 14.5 | 1263HWa0812544237 | NEW | yes | no | REI-M 60-A1 | 0 | no | 0 | no | Codetext | AllplanAttributes - ash D_Detailverweis: DT 3; ash D_Plannummer: D1615; Text1: SB3
 | H2 Ebene +4/ Dachebene | WI-LB | 1406Wa 0000005292 | yes | Codetext | m² | Trockenbauarbeiten | Wand | Innenwand 1-Schalig | WI-LB | 0 | A | 14.5 | 1263HWa0812544980 | NEW |  | no | REI 60-A1 - D,s2-d0 +A1 | 0 | no | 0 | no | Codetext | AllplanAttributes - ash_W_Trockenbau_Qualitäten: 9
 | H2 Ebene +4/ Dachebene | WI-HW 60 | 1406Wa 0000005348 | yes | Codetext | m² | Trockenbauarbeiten | Wand | Innenwand 1-Schalig | WI-HW 60 | 0 | A | 14.5 | 1263HWa0812546799 | NEW | yes | no | REI 60-A1 - A2,s1-d0 / A1 | 0 | no | 0 | no | Codetext
 | H2 Ebene +4/ Dachebene | WI-HW 60 | 1406Wa 0000005354 | yes | Codetext | m² | Trockenbauarbeiten | Wand | Innenwand 1-Schalig | WI-HW 60 | 0 | A | 14.5 | 1263HWa0812914546 | NEW | yes | no | REI 60-A1 - A2,s1-d0 / A1 | 0 | no | 47 | no | Codetext
 | H2 Ebene +4/ Dachebene | WI-LB | 1406Wa 0000005332 | yes | Codetext | m² | Trockenbauarbeiten | Wand | Innenwand 1-Schalig | WI-LB | 0 | A | 14.5 | 1263HWa0812544238 | NEW | no | no | REI 60-A1 - D,s2-d0 +A1 | 0 | no | 0 | no | Codetext | AllplanAttributes - ash_W_Trockenbau_Qualitäten: 9
 | H2 Ebene +4/ Dachebene | WI-STB | 1406Wa 0000005337 | yes | Codetext | m² | Betonarbeiten | Wand | Innenwand 1-Schalig | WI-STB | 0 | A | 14.5 | 1263HWa0812544238 | NEW | yes | no | REI 60-A1 - A2,s1-d0 / A1 | 0 | no | 0 | no | Codetext | AllplanAttributes - ash D_Detailverweis: DT 3; ash D_Plannummer: D1615; Text1: SB3
 | H2 Ebene +4/ Dachebene | WI-STB | 1406Wa 0000005319 | yes | Codetext | m² | Betonarbeiten | Wand | Innenwand 1-Schalig | WI-STB | 0 | A | 14.5 | 1263HWa0812609490 | NEW | yes | no | REI 60-A1 - A2,s1-d0 / A1 | 0 | no | 0 | no | Codetext
 | H2 Ebene +4/ Dachebene | WI-LB | 1406Wa 0000005315 | yes | Codetext | m² | Trockenbauarbeiten | Wand | Innenwand 1-Schalig | WI-LB | 0 | A | 14.5 | 1263HWa0812609490 | NEW | no | no | REI 60-A1 - D,s2-d0 +A1 | 0 | no | 0 | no | Codetext | AllplanAttributes - ash_W_Trockenbau_Qualitäten: 9
 | H2 Ebene +4/ Dachebene | WI-HW 60 | 1406Wa 0000005344 | yes | Codetext | m² | Trockenbauarbeiten | Wand | Innenwand 1-Schalig | WI-HW 60 | 0 | A | 14.5 | 1263HWa0812545263 | NEW | yes | no | REI 60-A1 - D,s2-d0 +A1 | 0 | no | 0 | no | Codetext
 | H2 Ebene +4/ Dachebene | WI-STB | 1406Wa 0000005326 | yes | Codetext | m² | Betonarbeiten | Wand | Innenwand 1-Schalig | WI-STB | 0 | A | 14.5 | 1263HWa0812544239 | NEW | yes | no | REI-M 60-A1 | 0 | no | 0 | no | Codetext | AllplanAttributes - ash D_Detailverweis: DT 3; ash D_Plannummer: D1615; Text1: SB3
 | H2 Ebene +4/ Dachebene | WI-LB | 1406Wa 0000004793 | yes | Codetext | m² | Trockenbauarbeiten | Wand | Innenwand 1-Schalig | WI-LB | 0 | A | 14.5 | 1263HWa0812545209 | NEW | no | no | REI 60-A1 - D,s2-d0 +A1 | 0 | no | 0 | no | Codetext | AllplanAttributes - W_Deckenanschluss: Gleitender Deckenanschluss Fall 01; ash_W_Trockenbau_Qualitäten: 1b
 | H2 Ebene +4/ Dachebene | WI-LB | 1406Wa 0000004814 | yes | Codetext | m² | Trockenbauarbeiten | Wand | Innenwand 1-Schalig | WI-LB | 0 | A | 14.5 | 1263HWa0812545201 | NEW | no | no | REI 60-A1 - A2,s1-d0 / A1 | 0 | no | 0 | no | Codetext | AllplanAttributes - W_Deckenanschluss: Gleitender Deckenanschluss Fall 01; ash_W_Trockenbau_Qualitäten: 1b
 | H2 Ebene +4/ Dachebene | WI-LB | 1406Wa 0000004797 | yes | Codetext | m² | Trockenbauarbeiten | Wand | Innenwand 1-Schalig | WI-LB | 0 | A | 14.5 | 1263HWa0812906742 | NEW | no | no | REI 60-A1 - D,s2-d0 +A1 | 0 | no | 0 | no | Codetext | AllplanAttributes - W_Deckenanschluss: Gleitender Deckenanschluss Fall 01; ash_W_Trockenbau_Qualitäten: 12b
 | H2 Ebene +4/ Dachebene | WI-LB | 1406Wa 0000004805 | yes | Codetext | m² | Trockenbauarbeiten | Wand | Innenwand 1-Schalig | WI-LB | 0 | A | 14.5 | 1263HWa0812843014 | NEW | no | no | REI 30 | 0 | no | 42 | no | Codetext | AllplanAttributes - W_Deckenanschluss: Gleitender Deckenanschluss Fall 01; ash_W_Trockenbau_Qualitäten: 18
 | H2 Ebene +4/ Dachebene | WI-LB | 1406Wa 0000004789 | yes | Codetext | m² | Trockenbauarbeiten | Wand | Innenwand 1-Schalig | WI-LB | 0 | A | 14.5 | 1263HWa0812843014 | NEW | no | no | REI 30 | 0 | no | 42 | no | Codetext | AllplanAttributes - W_Deckenanschluss: Gleitender Deckenanschluss Fall 01; ash_W_Trockenbau_Qualitäten: 18
 | H2 Ebene +4/ Dachebene | WI-LB | 1406Wa 0000004801 | yes | Codetext | m² | Trockenbauarbeiten | Wand | Innenwand 1-Schalig | WI-LB | 0 | A | 14.5 | 1263HWa0812731035 | NEW | no | no | REI 60-A1 - A2,s1-d0 / A1 | 0 | no | 0 | no | Codetext | AllplanAttributes - W_Deckenanschluss: Gleitender Deckenanschluss Fall 01; ash_W_Trockenbau_Qualitäten: 1b
 | H2 Ebene +4/ Dachebene | WI-LB | 1406Wa 0000004809 | yes | Codetext | m² | Trockenbauarbeiten | Wand | Innenwand 1-Schalig | WI-LB | 0 | A | 14.5 | 1263HWa0812545201 | NEW | no | no | REI 60-A1 - A2,s1-d0 / A1 | 0 | no | 0 | no | Codetext | AllplanAttributes - W_Deckenanschluss: Gleitender Deckenanschluss Fall 01; ash_W_Trockenbau_Qualitäten: 1b
 | H2 Ebene +4/ Dachebene | WI-LB | 1406Wa 0000004818 | yes | Codetext | m² | Trockenbauarbeiten | Wand | Innenwand 1-Schalig | WI-LB | 0 | A | 14.5 | 1263HWa0812545193 | NEW | no | no | REI 60-A1 - D,s2-d0 +A1 | 0 | no | 0 | no | Codetext | AllplanAttributes - W_Deckenanschluss: Gleitender Deckenanschluss Fall 01; ash_W_Trockenbau_Qualitäten: 1a
 | H2 Ebene +4/ Dachebene | WI-LB | 1406Wa 0000004830 | yes | Codetext | m² | Trockenbauarbeiten | Wand | Innenwand 1-Schalig | WI-LB | 0 | A | 14.5 | 1263HWa0812545201 | NEW | no | no | REI 60-A1 - A2,s1-d0 / A1 | 0 | no | 0 | no | Codetext | AllplanAttributes - W_Deckenanschluss: Gleitender Deckenanschluss Fall 01; ash_W_Trockenbau_Qualitäten: 1b
 | H2 Ebene +4/ Dachebene | WI-LB | 1406Wa 0000004823 | yes | Codetext | m² | Trockenbauarbeiten | Wand | Innenwand 1-Schalig | WI-LB | 0 | A | 14.5 | 1263HWa0812545201 | NEW | no | no | REI 60-A1 - A2,s1-d0 / A1 | 0 | no | 0 | no | Codetext | AllplanAttributes - W_Deckenanschluss: Gleitender Deckenanschluss Fall 01; ash_W_Trockenbau_Qualitäten: 1b
 | H2 Ebene +4/ Dachebene | WI-LB | 1406Wa 0000004826 | yes | Codetext | m² | Trockenbauarbeiten | Wand | Innenwand 1-Schalig | WI-LB | 0 | A | 14.5 | 1263HWa0812544148 | NEW | no | no | REI 60-A1 - A2,s1-d0 / A1 | 0 | no | 0 | no | Codetext | AllplanAttributes - W_Deckenanschluss: Gleitender Deckenanschluss Fall 01; ash_W_Trockenbau_Qualitäten: 1b
 | H2 Ebene +4/ Dachebene | WI-LB | 1406Wa 0000004833 | yes | Codetext | m² | Trockenbauarbeiten | Wand | Innenwand 1-Schalig | WI-LB | 0 | A | 14.5 | 1263HWa0812544133 | NEW | no | no | REI 60-A1 - A2,s1-d0 / A1 | 0 | no | 0 | no | Codetext | AllplanAttributes - W_Deckenanschluss: Gleitender Deckenanschluss Fall 01; ash_W_Trockenbau_Qualitäten: 1b
 | H2 Ebene +4/ Dachebene | WI-LB | 1406Wa 0000004838 | yes | Codetext | m² | Trockenbauarbeiten | Wand | Innenwand 1-Schalig | WI-LB | 0 | A | 14.5 | 1263HWa0812544132 | NEW | no | no | REI 60-A1 - A2,s1-d0 / A1 | 0 | no | 0 | no | Codetext | AllplanAttributes - W_Deckenanschluss: Gleitender Deckenanschluss Fall 01; ash_W_Trockenbau_Qualitäten: 1b
 | H2 Ebene +4/ Dachebene | WI-LB | 1406Wa 0000004844 | yes | Codetext | m² | Trockenbauarbeiten | Wand | Innenwand 1-Schalig | WI-LB | 0 | A | 14.5 | 1263HWa0812544105 | NEW | no | no | REI 60-A1 - A2,s1-d0 / A1 | 0 | no | 0 | no | Codetext | AllplanAttributes - W_Deckenanschluss: Gleitender Deckenanschluss Fall 01; ash_W_Trockenbau_Qualitäten: 1b
 | H2 Ebene +4/ Dachebene | Installationsraum | 1406Wa 0000004841 | yes | Codetext | m² | Trockenbauarbeiten | Wand | Installationswand | Installationsraum | 0 | A | 14.5 | 1263HWa0812601943 | NEW | no | no | 0 | 0 | no | 0 | no | Codetext | AllplanAttributes - W_Deckenanschluss: Gleitender Deckenanschluss Fall 01
 | H2 Ebene +4/ Dachebene | WI-VS | 1406Wa 0000004847 | yes | Codetext | m² | Trockenbauarbeiten | Wand | Installationswand | WI-VS | 0 | A | 14.5 | 1263HWa0812601943 | NEW | no | no | 0 | 0 | no | 0 | no | Codetext | AllplanAttributes - W_Deckenanschluss: Gleitender Deckenanschluss Fall 01; ash_W_Trockenbau_Qualitäten: 2
 | H2 Ebene +4/ Dachebene | WI-LB | 1406Wa 0000004202 | yes | Codetext | m² | Trockenbauarbeiten | Wand | Innenwand 1-Schalig | WI-LB | 0 | A | 14.5 | 1263HWa0812544104 | NEW | no | no | REI 60-A1 - A2,s1-d0 / A1 | 0 | no | 0 | no | Codetext | AllplanAttributes - W_Deckenanschluss: Gleitender Deckenanschluss Fall 01; ash_W_Trockenbau_Qualitäten: 1b
 | H2 Ebene +4/ Dachebene | WI-HW 60 | 1406Wa 0000004207 | yes | Codetext | m² | Trockenbauarbeiten | Wand | Innenwand 1-Schalig | WI-HW 60 | 0 | A | 14.5 | 1263HWa0812544482 | NEW | yes | no | REI-M 60-D,s2,d0 + A1 | 0 | no | 0 | no | Codetext | AllplanAttributes - ash D_Detailverweis: DT 8; ash D_Plannummer: D1613
 | H2 Ebene +4/ Dachebene | WI-LW 60 | 1406Wa 0000005496 | yes | Codetext | m² | Trockenbauarbeiten | Wand | Innenwand 1-Schalig | WI-LW 60 | 0 | A | 14.5 | 1263HWa0812546608 | NEW | no | no | REI-M 60-D,s2,d0 + A1 | 0 | no | 0 | no | Codetext | AllplanAttributes - ash_W_Trockenbau_Qualitäten: 12a
 | H2 Ebene +4/ Dachebene | WI-HW 60 | 1406Wa 0000005493 | yes | Codetext | m² | Trockenbauarbeiten | Wand | Innenwand 1-Schalig | WI-HW 60 | 0 | A | 14.5 | 1263HWa0812546505 | NEW | no | no | REI-M 60-D,s2,d0 + A1 | 0 | no | 0 | no | Codetext
 | H2 Ebene +4/ Dachebene | WI-HW 60 | 1406Wa 0000005469 | yes | Codetext | m² | Trockenbauarbeiten | Wand | Innenwand 1-Schalig | WI-HW 60 | 0 | A | 14.5 | 1263HWa0812546507 | NEW | no | no | REI-M 60-D,s2,d0 + A1 | 0 | no | 0 | no | Codetext | AllplanAttributes - ash D_Detailverweis: DT 7; ash D_Plannummer: D1613
 | H2 Ebene +4/ Dachebene | WI-LB | 1406Wa 0000005525 | yes | Codetext | m² | Trockenbauarbeiten | Wand | Innenwand 1-Schalig | WI-LB | 0 | A | 14.5 | 1263HWa0812544127 | NEW | no | no | REI 60-A1 - A2,s1-d0 / A1 | 0 | no | 0 | no | Codetext | AllplanAttributes - W_Deckenanschluss: Gleitender Deckenanschluss Fall 01; ash_W_Trockenbau_Qualitäten: 1b
 | H2 Ebene +4/ Dachebene | WI-HW 60 | 1406Wa 0000005477 | yes | Codetext | m² | Trockenbauarbeiten | Wand | Innenwand 1-Schalig | WI-HW 60 | 0 | A | 14.5 | 1263HWa0812546525 | NEW | no | no | REI-M 60-D,s2,d0 + A1 | 0 | no | 0 | no | Codetext | AllplanAttributes - ash D_Detailverweis: DT 8; ash D_Plannummer: D1613
 | H2 Ebene +4/ Dachebene | WI-LB | 1406Wa 0000005487 | yes | Codetext | m² | Trockenbauarbeiten | Wand | Innenwand 1-Schalig | WI-LB | 0 | A | 14.5 | 1263HWa0812545193 | NEW | no | no | REI 60-A1 - D,s2-d0 +A1 | 0 | no | 0 | no | Codetext | AllplanAttributes - W_Deckenanschluss: Gleitender Deckenanschluss Fall 01; ash_W_Trockenbau_Qualitäten: 1b
 | H2 Ebene +4/ Dachebene | WI-LB | 1406Wa 0000005529 | yes | Codetext | m² | Trockenbauarbeiten | Wand | Innenwand 1-Schalig | WI-LB | 0 | A | 14.5 | 1263HWa0812730977 | NEW | no | no | REI 60-A1 - A2,s1-d0 / A1 | 0 | no | 0 | no | Codetext | AllplanAttributes - W_Deckenanschluss: Gleitender Deckenanschluss Fall 01; ash_W_Trockenbau_Qualitäten: 1b
 | H2 Ebene +4/ Dachebene | WI-LB | 1406Wa 0000005481 | yes | Codetext | m² | Trockenbauarbeiten | Wand | Innenwand 1-Schalig | WI-LB | 0 | A | 14.5 | 1263HWa0812545216 | NEW | no | no | REI 60-A1 - A2,s1-d0 / A1 | 0 | no | 0 | no | Codetext | AllplanAttributes - W_Deckenanschluss: Gleitender Deckenanschluss Fall 01; ash_W_Trockenbau_Qualitäten: 1b
 | H2 Ebene +4/ Dachebene | WI-LB | 1406Wa 0000005473 | yes | Codetext | m² | Trockenbauarbeiten | Wand | Innenwand 1-Schalig | WI-LB | 0 | A | 14.5 | 1263HWa0812545193 | NEW | no | no | REI 60-A1 - D,s2-d0 +A1 | 0 | no | 0 | no | Codetext | AllplanAttributes - W_Deckenanschluss: Gleitender Deckenanschluss Fall 01; ash_W_Trockenbau_Qualitäten: 1a
 | H2 Ebene +4/ Dachebene | WI-LB | 1406Wa 0000005491 | yes | Codetext | m² | Trockenbauarbeiten | Wand | Innenwand 1-Schalig | WI-LB | 0 | A | 14.5 | 1263HWa0812545193 | NEW | no | no | REI 60-A1 - D,s2-d0 +A1 | 0 | no | 0 | no | Codetext | AllplanAttributes - W_Deckenanschluss: Gleitender Deckenanschluss Fall 01; ash_W_Trockenbau_Qualitäten: 1b
 | H2 Ebene +4/ Dachebene | WI-LB | 1406Wa 0000005535 | yes | Codetext | m² | Trockenbauarbeiten | Wand | Innenwand 1-Schalig | WI-LB | 0 | A | 14.5 | 1263HWa0812545193 | NEW | no | no | REI 60-A1 - D,s2-d0 +A1 | 0 | no | 0 | no | Codetext | AllplanAttributes - W_Deckenanschluss: Gleitender Deckenanschluss Fall 01; ash_W_Trockenbau_Qualitäten: 1b
 | H2 Ebene +4/ Dachebene | WI-LB | 1406Wa 0000005463 | yes | Codetext | m² | Trockenbauarbeiten | Wand | Innenwand 1-Schalig | WI-LB | 0 | A | 14.5 | 1263HWa0812544221 | NEW | no | no | REI 60-A1 - A2,s1-d0 / A1 | 0 | no | 0 | no | Codetext | AllplanAttributes - W_Deckenanschluss: Gleitender Deckenanschluss Fall 01; ash_W_Trockenbau_Qualitäten: 1b
 | H2 Ebene +4/ Dachebene | WI-LB | 1406Wa 0000005466 | yes | Codetext | m² | Trockenbauarbeiten | Wand | Innenwand 1-Schalig | WI-LB | 0 | A | 14.5 | 1263HWa0812544128 | NEW | no | no | REI 60-A1 - A2,s1-d0 / A1 | 0 | no | 0 | no | Codetext | AllplanAttributes - W_Deckenanschluss: Gleitender Deckenanschluss Fall 01; ash_W_Trockenbau_Qualitäten: 1b
 | H2 Ebene +4/ Dachebene | WI-LB | 1406Wa 0000005506 | yes | Codetext | m² | Trockenbauarbeiten | Wand | Innenwand 1-Schalig | WI-LB | 0 | A | 14.5 | 1263HWa0812544126 | NEW | no | no | REI 60-A1 - A2,s1-d0 / A1 | 0 | no | 0 | no | Codetext | AllplanAttributes - W_Deckenanschluss: Gleitender Deckenanschluss Fall 01; ash_W_Trockenbau_Qualitäten: 1b
 | H2 Ebene +4/ Dachebene | WI-LB | 1406Wa 0000005501 | yes | Codetext | m² | Trockenbauarbeiten | Wand | Innenwand 1-Schalig | WI-LB | 0 | A | 14.5 | 1263HWa0812544103 | NEW | no | no | REI 60-A1 - A2,s1-d0 / A1 | 0 | no | 0 | no | Codetext | AllplanAttributes - W_Deckenanschluss: Gleitender Deckenanschluss Fall 01; ash_W_Trockenbau_Qualitäten: 1b
 | H2 Ebene +4/ Dachebene | WI-LB | 1406Wa 0000005510 | yes | Codetext | m² | Trockenbauarbeiten | Wand | Innenwand 1-Schalig | WI-LB | 0 | A | 14.5 | 1263HWa0812545194 | NEW | no | no | REI 60-A1 - A2,s1-d0 / A1 | 0 | no | 0 | no | Codetext | AllplanAttributes - W_Deckenanschluss: Gleitender Deckenanschluss Fall 01; ash_W_Trockenbau_Qualitäten: 1b
 | H2 Ebene +4/ Dachebene | WI-LB | 1406Wa 0000005932 | yes | Codetext | m² | Trockenbauarbeiten | Wand | Innenwand 1-Schalig | WI-LB | 0 | A | 14.5 | 1263HWa0812545273 | NEW | no | no | REI 60-A1 - D,s2-d0 +A1 | 0 | no | 42 | no | Codetext | AllplanAttributes - W_Deckenanschluss: Gleitender Deckenanschluss Fall 01; ash_W_Trockenbau_Qualitäten: 1b
 | H2 Ebene +4/ Dachebene | Installationsraum | 1406Wa 0000005937 | yes | Codetext | m² | Trockenbauarbeiten | Wand | Installationswand | Installationsraum | 0 | A | 14.5 | 1263HWa0812772336 | NEW | no | no | 0 | 0 | no | 0 | no | Codetext | AllplanAttributes - W_Deckenanschluss: Gleitender Deckenanschluss Fall 01
 | H2 Ebene +4/ Dachebene | WI-VS | 1406Wa 0000004428 | yes | Codetext | m² | Trockenbauarbeiten | Wand | Installationswand | WI-VS | 0 | A | 14.5 | 1263HWa0812772336 | NEW | no | no | 0 | 0 | no | 0 | no | Codetext | AllplanAttributes - W_Deckenanschluss: Gleitender Deckenanschluss Fall 01; ash_W_Trockenbau_Qualitäten: 2
 | H2 Ebene +4/ Dachebene | WI-LB | 1406Wa 0000006329 | yes | Codetext | m² | Trockenbauarbeiten | Wand | Innenwand 1-Schalig | WI-LB | 0 | A | 14.5 | 1263HWa0812594456 | NEW | no | no | 0 | 0 | no | 42 | no | Codetext | AllplanAttributes - W_Deckenanschluss: Gleitender Deckenanschluss Fall 01; ash_W_Trockenbau_Qualitäten: 11
 | H2 Ebene +4/ Dachebene | WI-LB | 1406Wa 0000004433 | yes | Codetext | m² | Trockenbauarbeiten | Wand | Innenwand 1-Schalig | WI-LB | 0 | A | 14.5 | 1263HWa0812594456 | NEW | no | no | 0 | 0 | no | 42 | no | Codetext | AllplanAttributes - W_Deckenanschluss: Gleitender Deckenanschluss Fall 01; ash_W_Trockenbau_Qualitäten: 10a
 | H2 Ebene +4/ Dachebene | Installationsraum | 1406Wa 0000006326 | yes | Codetext | m² | Trockenbauarbeiten | Wand | Installationswand | Installationsraum | 0 | A | 14.5 | 1263HWa0812839368 | NEW | no | no | 0 | 0 | no | 0 | no | Codetext | AllplanAttributes - W_Deckenanschluss: Gleitender Deckenanschluss Fall 01
 | H2 Ebene +4/ Dachebene | WI-VS | 1406Wa 0000006340 | yes | Codetext | m² | Trockenbauarbeiten | Wand | Installationswand | WI-VS | 0 | A | 14.5 | 1263HWa0812839368 | NEW | no | no | 0 | 0 | no | 0 | no | Codetext | AllplanAttributes - W_Deckenanschluss: Gleitender Deckenanschluss Fall 01; ash_W_Trockenbau_Qualitäten: 3
 | H2 Ebene +4/ Dachebene | Installationsraum | 1406Wa 0000006320 | yes | Codetext | m² | Trockenbauarbeiten | Wand | Installationswand | Installationsraum | 0 | A | 14.5 | 1263HWa0812839396 | NEW | no | no | 0 | 0 | no | 0 | no | Codetext | AllplanAttributes - W_Deckenanschluss: Gleitender Deckenanschluss Fall 01
 | H2 Ebene +4/ Dachebene | WI-VS | 1406Wa 0000006324 | yes | Codetext | m² | Trockenbauarbeiten | Wand | Installationswand | WI-VS | 0 | A | 14.5 | 1263HWa0812839396 | NEW | no | no | 0 | 0 | no | 0 | no | Codetext | AllplanAttributes - W_Deckenanschluss: Gleitender Deckenanschluss Fall 01; ash_W_Trockenbau_Qualitäten: 3
 | H2 Ebene +4/ Dachebene | WI-LB | 1406Wa 0000006344 | yes | Codetext | m² | Trockenbauarbeiten | Wand | Innenwand 1-Schalig | WI-LB | 0 | A | 14.5 | 1263HWa0812833053 | NEW | no | no | 0 | 0 | no | 42 | no | Codetext | AllplanAttributes - W_Deckenanschluss: Gleitender Deckenanschluss Fall 01; ash_W_Trockenbau_Qualitäten: 10a
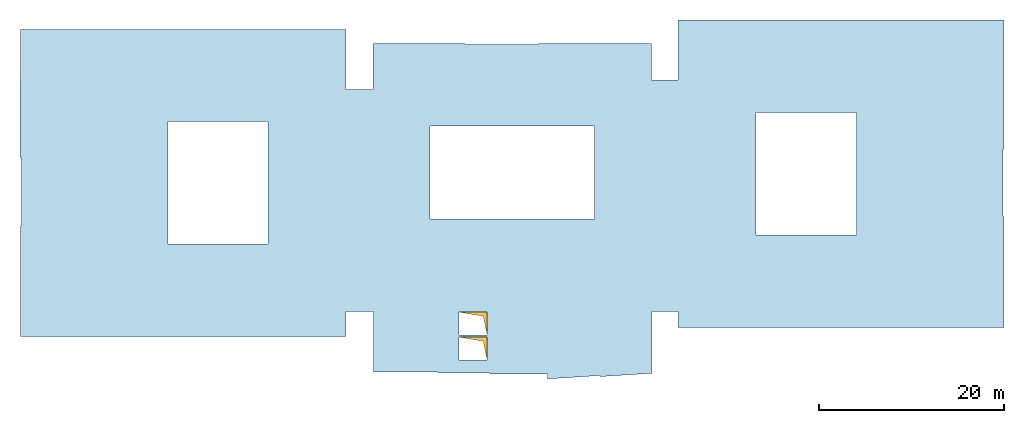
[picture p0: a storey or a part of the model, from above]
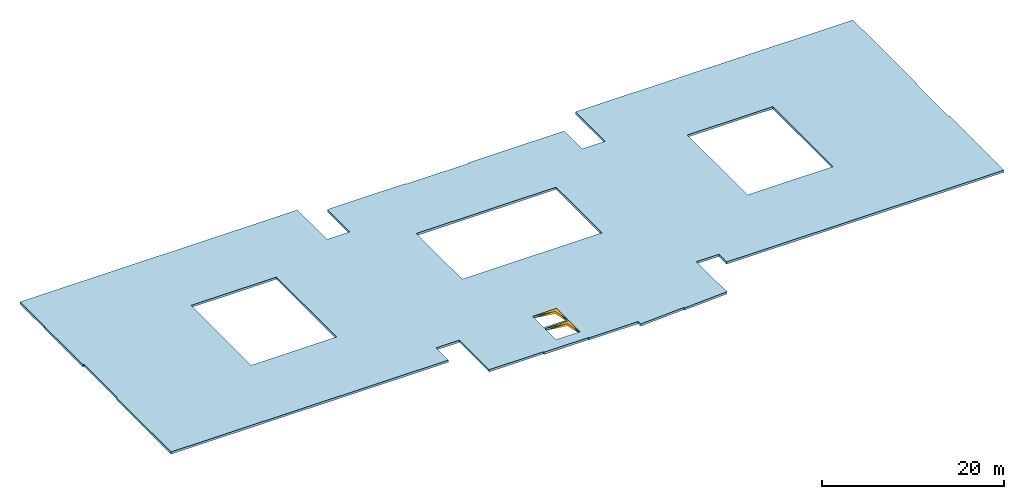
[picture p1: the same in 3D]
Properties of the parts of a building model (IFC4), part 44 of 80

# IfcWall (6826)
Name | In | Material | Allright_Bauteil_ID | 2D Interaktion | Codetext | Abrechnungsart | Gewerk | Objektname | Bezeichnung | AllplanAttributes, Material | Typ = SurfaceSpreadOfFlame | Brandschutzklasse | OKFF | P_ID | Status | LoadBearing | IsExternal | FireRating | ThermalTransmittance (W/K/m2) | Combustible | AcousticRating | Compartmentation | Reference
 | H2 Ebene +4/ Dachebene | WI-LB | 1406Wa 0000006336 | yes | Codetext | m² | Trockenbauarbeiten | Wand | Innenwand 1-Schalig | WI-LB | 0 | A | 14.5 | 1263HWa0812839278 | NEW | no | no | 0 | 0 | no | 42 | no | Codetext | AllplanAttributes - W_Deckenanschluss: Gleitender Deckenanschluss Fall 01; ash_W_Trockenbau_Qualitäten: 10a
 | H2 Ebene +4/ Dachebene | WI-STB | 1406Wa 0000005941 | yes | Codetext | m² | Betonarbeiten | Wand | Innenwand 1-Schalig | WI-STB | 0 | A | 14.5 | 1263HWa0812545224 | NEW | yes | no | REI 60-A1 - A2,s1-d0 / A1 | 0 | no | 42 | yes | Codetext
 | H2 Ebene +4/ Dachebene | WI-STB | 1406Wa 0000006002 | yes | Codetext | m² | Betonarbeiten | Wand | Innenwand 1-Schalig | WI-STB | 0 | A | 14.5 | 1263HWa0812545399 | NEW | yes | no | REI 60-A1 - A2,s1-d0 / A1 | 0 | no | 42 | yes | Codetext
 | H2 Ebene +4/ Dachebene | WI-LB | 1406Wa 0000005978 | yes | Codetext | m² | Trockenbauarbeiten | Wand | Innenwand 1-Schalig | WI-LB | 0 | A | 14.5 | 1263HWa0812786486 | NEW | no | no | REI 60-A1 - A2,s1-d0 / A1 | 0 | no | 42 | no | Codetext | AllplanAttributes - W_Deckenanschluss: Gleitender Deckenanschluss Fall 01; ash_W_Trockenbau_Qualitäten: 13
 | H2 Ebene +4/ Dachebene | WI-LB | 1406Wa 0000005952 | yes | Codetext | m² | Trockenbauarbeiten | Wand | Innenwand 1-Schalig | WI-LB | 0 | A | 14.5 | 1263HWa0812545272 | NEW | no | no | REI 30 | 0 | no | 42 | no | Codetext | AllplanAttributes - W_Deckenanschluss: Gleitender Deckenanschluss Fall 01; ash_W_Trockenbau_Qualitäten: 1b
 | H2 Ebene +4/ Dachebene | WI-LB | 1406Wa 0000005989 | yes | Codetext | m² | Trockenbauarbeiten | Wand | Innenwand 1-Schalig | WI-LB | 0 | A | 14.5 | 1263HWa0812544980 | NEW |  | no | REI 60-A1 - D,s2-d0 +A1 | 0 | no | 0 | no | Codetext | AllplanAttributes - ash_W_Trockenbau_Qualitäten: 9
 | H2 Ebene +4/ Dachebene | WI-HW 60 | 1406Wa 0000004443 | yes | Codetext | m² | Trockenbauarbeiten | Wand | Innenwand 1-Schalig | WI-HW 60 | 0 | A | 14.5 | 1263HWa0812824830 | NEW | yes | no | REI-M 60-D,s2,d0 + A1 | 0 | no | 42 | no | Codetext | AllplanAttributes - ash D_Detailverweis: DT 8; ash D_Plannummer: D1613
 | H2 Ebene +4/ Dachebene | WI-HW 60 | 1406Wa 0000004485 | yes | Codetext | m² | Trockenbauarbeiten | Wand | Innenwand 1-Schalig | WI-HW 60 | 0 | A | 14.5 | 1263HWa0812546998 | NEW | yes | no | REI-M 60-D,s2,d0 + A1 | 0 | no | 42 | no | Codetext | AllplanAttributes - ash D_Detailverweis: DT 7; ash D_Plannummer: D1613
 | H2 Ebene +4/ Dachebene | Installationsraum | 1406Wa 0000005987 | yes | Codetext | m² | Trockenbauarbeiten | Wand | Installationswand | Installationsraum | 0 | A | 14.5 | 1263HWa0812769872 | NEW | no | no | 0 | 0 | no | 0 | no | Codetext | AllplanAttributes - W_Deckenanschluss: Gleitender Deckenanschluss Fall 01
 | H2 Ebene +4/ Dachebene | WI-VS | 1406Wa 0000005982 | yes | Codetext | m² | Trockenbauarbeiten | Wand | Installationswand | WI-VS | 0 | A | 14.5 | 1263HWa0812769872 | NEW | no | no | 0 | 0 | no | 0 | no | Codetext | AllplanAttributes - W_Deckenanschluss: Gleitender Deckenanschluss Fall 01; ash_W_Trockenbau_Qualitäten: 3
 | H2 Ebene +4/ Dachebene | Installationsraum | 1406Wa 0000004476 | yes | Codetext | m² | Trockenbauarbeiten | Wand | Installationswand | Installationsraum | 0 | A | 14.5 | 1263HWa0812840778 | NEW | no | no | 0 | 0 | no | 0 | no | Codetext | AllplanAttributes - W_Deckenanschluss: Gleitender Deckenanschluss Fall 01
 | H2 Ebene +4/ Dachebene | WI-VS | 1406Wa 0000004456 | yes | Codetext | m² | Trockenbauarbeiten | Wand | Installationswand | WI-VS | 0 | A | 14.5 | 1263HWa0812840778 | NEW | no | no | 0 | 0 | no | 0 | no | Codetext | AllplanAttributes - W_Deckenanschluss: Gleitender Deckenanschluss Fall 01; ash_W_Trockenbau_Qualitäten: 3
 | H2 Ebene +4/ Dachebene | WI-LB | 1406Wa 0000005946 | yes | Codetext | m² | Trockenbauarbeiten | Wand | Innenwand 1-Schalig | WI-LB | 0 | A | 14.5 | 1263HWa0812546999 | NEW | no | no | REI 30 | 0 | no | 42 | no | Codetext | AllplanAttributes - W_Deckenanschluss: Gleitender Deckenanschluss Fall 01; ash_W_Trockenbau_Qualitäten: 1b
 | H2 Ebene +4/ Dachebene | WI-HW 60 | 1406Wa 0000004472 | yes | Codetext | m² | Trockenbauarbeiten | Wand | Innenwand 1-Schalig | WI-HW 60 | 0 | A | 14.5 | 1263HWa0812824923 | NEW | yes | no | REI-M 60-D,s2,d0 + A1 | 0 | no | 42 | no | Codetext | AllplanAttributes - ash D_Detailverweis: DT 8; ash D_Plannummer: D1613
 | H2 Ebene +4/ Dachebene | Installationsraum | 1406Wa 0000004452 | yes | Codetext | m² | Trockenbauarbeiten | Wand | Installationswand | Installationsraum | 0 | A | 14.5 | 1263HWa0812840743 | NEW | no | no | 0 | 0 | no | 0 | no | Codetext | AllplanAttributes - W_Deckenanschluss: Gleitender Deckenanschluss Fall 01
 | H2 Ebene +4/ Dachebene | WI-VS | 1406Wa 0000004447 | yes | Codetext | m² | Trockenbauarbeiten | Wand | Installationswand | WI-VS | 0 | A | 14.5 | 1263HWa0812840743 | NEW | no | no | 0 | 0 | no | 0 | no | Codetext | AllplanAttributes - W_Deckenanschluss: Gleitender Deckenanschluss Fall 01; ash_W_Trockenbau_Qualitäten: 3
 | H2 Ebene +4/ Dachebene | WI-VS | 1406Wa 0000012178 | yes | Codetext | m² | Trockenbauarbeiten | Wand | Installationswand | WI-VS | 0 | A | 14.5 | 1263HWa0812840778 | NEW | no | no | 0 | 0 | no | 0 | no | Codetext | AllplanAttributes - W_Deckenanschluss: Gleitender Deckenanschluss Fall 01; ash_W_Trockenbau_Qualitäten: 3
 | H2 Ebene +4/ Dachebene | WI-LW 60 | 1406Wa 0000004466 | yes | Codetext | m² | Trockenbauarbeiten | Wand | Innenwand 1-Schalig | WI-LW 60 | 0 | A | 14.5 | 1263HWa0812547005 | NEW | yes | no | REI-M 60-D,s2,d0 + A1 | 0 | no | 0 | no | Codetext | AllplanAttributes - ash_W_Trockenbau_Qualitäten: 12a
 | H2 Ebene +4/ Dachebene | WI-LB | 1406Wa 0000004480 | yes | Codetext | m² | Trockenbauarbeiten | Wand | Innenwand 1-Schalig | WI-LB | 0 | A | 14.5 | 1263HWa0812843014 | NEW | no | no | REI 30 | 0 | no | 42 | no | Codetext | AllplanAttributes - W_Deckenanschluss: Gleitender Deckenanschluss Fall 01; ash_W_Trockenbau_Qualitäten: 1b
 | H2 Ebene +4/ Dachebene | WI-HW 60 | 1406Wa 0000005927 | yes | Codetext | m² | Trockenbauarbeiten | Wand | Innenwand 1-Schalig | WI-HW 60 | 0 | A | 14.5 | 1263HWa0812545527 | NEW | yes | no | REI 60-A1 - D,s2-d0 +A1 | 0 | no | 0 | no | Codetext | AllplanAttributes - ash D_Detailverweis: DT 8; ash D_Plannummer: D1613
 | H2 Ebene +4/ Dachebene | WI-STB | 1406Wa 0000004216 | yes | Codetext | m² | Betonarbeiten | Wand | Innenwand 1-Schalig | WI-STB | 0 | A | 14.5 | 1263HWa0812545467 | NEW | yes | no | REI-M 60-A1 | 0 | no | 0 | no | Codetext | AllplanAttributes - ash D_Detailverweis: DT 5; ash D_Plannummer: D1614; Text1: SB3
 | H2 Ebene +4/ Dachebene | WI-STB | 1406Wa 0000004234 | yes | Codetext | m² | Betonarbeiten | Wand | Innenwand 1-Schalig | WI-STB | 0 | A | 14.5 | 1263HWa0812546934 | NEW | yes | no | REI-M 60-A1 | 0 | no | 0 | yes | Codetext | AllplanAttributes - ash D_Detailverweis: DT 3; ash D_Plannummer: D1615; Text1: SB3
 | H2 Ebene +4/ Dachebene | WA-STB | 1406Wa 0000004192 | yes | Codetext | m² | Betonarbeiten | Wand | Innenwand 1-Schalig | WA-STB | 0 | A | 14.5 | 1263HWa0812545465 | NEW | yes | no | REI-M 60-A1 | 0 | no | 0 | no | Codetext | AllplanAttributes - ash D_Detailverweis: DT 6; ash D_Plannummer: D1613; Text1: SB3
 | H2 Ebene +4/ Dachebene | WI-STB | 1406Wa 0000004178 | yes | Codetext | m² | Betonarbeiten | Wand | Innenwand 1-Schalig | WI-STB | 0 | A | 14.5 | 1263HWa0812545524 | NEW | no | no | REI 60-A1 - A2,s1-d0 / A1 | 0 | no | 0 | no | Codetext | AllplanAttributes - Text1: SB3
 | H2 Ebene +4/ Dachebene | WI-LB | 1406Wa 0000004176 | yes | Codetext | m² | Trockenbauarbeiten | Wand | Innenwand 1-Schalig | WI-LB | 0 | A | 14.5 | 1263HWa0812545524 | NEW | no | no | REI 60-A1 - D,s2-d0 +A1 | 0 | no | 0 | no | Codetext
 | H2 Ebene +4/ Dachebene | WI-HW 60 | 1406Wa 0000004196 | yes | Codetext | m² | Trockenbauarbeiten | Wand | Innenwand 1-Schalig | WI-HW 60 | 0 | A | 14.5 | 1263HWa0812602159 | NEW | yes | no | REI-M 60-D,s2,d0 + A1 | 0 | no | 0 | no | Codetext | AllplanAttributes - ash D_Detailverweis: DT 7; ash D_Plannummer: D1613
 | H2 Ebene +4/ Dachebene | WI-LB | 1406Wa 0000005914 | yes | Codetext | m² | Trockenbauarbeiten | Wand | Innenwand 1-Schalig | WI-LB | 0 | A | 14.5 | 1263HWa0812594301 | NEW | no | no | 0 | 0 | no | 0 | no | Codetext | AllplanAttributes - W_Deckenanschluss: Gleitender Deckenanschluss Fall 01; ash_W_Trockenbau_Qualitäten: 1b
 | H2 Ebene +4/ Dachebene | WI-LB | 1406Wa 0000004403 | yes | Codetext | m² | Trockenbauarbeiten | Wand | Innenwand 1-Schalig | WI-LB | 0 | A | 14.5 | 1263HWa0812594383 | NEW | no | no | REI 60-A1 - D,s2-d0 +A1 | 0 | no | 42 | no | Codetext | AllplanAttributes - W_Deckenanschluss: Gleitender Deckenanschluss Fall 01; ash_W_Trockenbau_Qualitäten: 1b
 | H2 Ebene +4/ Dachebene | WI-LB | 1406Wa 0000004507 | yes | Codetext | m² | Trockenbauarbeiten | Wand | Innenwand 1-Schalig | WI-LB | 0 | A | 14.5 | 1263HWa0812545256 | NEW | no | no | REI 60-A1 - D,s2-d0 +A1 | 0 | no | 0 | no | Codetext | AllplanAttributes - W_Deckenanschluss: Gleitender Deckenanschluss Fall 01; ash_W_Trockenbau_Qualitäten: 1b
 | H2 Ebene +4/ Dachebene | WI-STB | 1406Wa 0000004400 | yes | Codetext | m² | Betonarbeiten | Wand | Innenwand 1-Schalig | WI-STB | 0 | A | 14.5 | 1263HWa0812547294 | NEW | yes | no | REI 60-A1 - A2,s1-d0 / A1 | 0 | no | 0 | yes | Codetext
 | H2 Ebene +4/ Dachebene | WI-STB | 1406Wa 0000006035 | yes | Codetext | m² | Betonarbeiten | Wand | Innenwand 1-Schalig | WI-STB | 0 | A | 14.5 | 1263HWa0812547294 | NEW | yes | no | REI 60-A1 - A2,s1-d0 / A1 | 0 | no | 0 | yes | Codetext
 | H2 Ebene +4/ Dachebene | WI-STB | 1406Wa 0000006047 | yes | Codetext | m² | Betonarbeiten | Wand | Innenwand 1-Schalig | WI-STB | 0 | A | 14.5 | 1263HWa0812547294 | NEW | yes | no | REI 60-A1 - A2,s1-d0 / A1 | 0 | no | 0 | yes | Codetext
 | H2 Ebene +4/ Dachebene | WI-LB | 1406Wa 0000004502 | yes | Codetext | m² | Trockenbauarbeiten | Wand | Innenwand 1-Schalig | WI-LB | 0 | A | 14.5 | 1263HWa0812544980 | NEW |  | no | REI 60-A1 - D,s2-d0 +A1 | 0 | no | 0 | no | Codetext | AllplanAttributes - ash_W_Trockenbau_Qualitäten: 9
 | H2 Ebene +4/ Dachebene | WI-LB | 1406Wa 0000004416 | yes | Codetext | m² | Trockenbauarbeiten | Wand | Innenwand 1-Schalig | WI-LB | 0 | A | 14.5 | 1263HWa0812593394 | NEW | no | no | 0 | 0 | no | 42 | no | Codetext | AllplanAttributes - W_Deckenanschluss: Gleitender Deckenanschluss Fall 01; ash_W_Trockenbau_Qualitäten: 10a
 | H2 Ebene +4/ Dachebene | WI-LB | 1406Wa 0000006044 | yes | Codetext | m² | Trockenbauarbeiten | Wand | Innenwand 1-Schalig | WI-LB | 0 | A | 14.5 | 1263HWa0812544980 | NEW |  | no | REI 60-A1 - D,s2-d0 +A1 | 0 | no | 0 | no | Codetext | AllplanAttributes - ash_W_Trockenbau_Qualitäten: 9
 | H2 Ebene +4/ Dachebene | WI-LB | 1406Wa 0000006030 | yes | Codetext | m² | Trockenbauarbeiten | Wand | Innenwand 1-Schalig | WI-LB | 0 | A | 14.5 | 1263HWa0812786486 | NEW | no | no | REI 60-A1 - A2,s1-d0 / A1 | 0 | no | 42 | no | Codetext | AllplanAttributes - W_Deckenanschluss: Gleitender Deckenanschluss Fall 01; ash_W_Trockenbau_Qualitäten: 13
 | H2 Ebene +4/ Dachebene | Installationsraum | 1406Wa 0000006040 | yes | Codetext | m² | Trockenbauarbeiten | Wand | Installationswand | Installationsraum | 0 | A | 14.5 | 1263HWa0812769295 | NEW | no | no | 0 | 0 | no | 0 | no | Codetext | AllplanAttributes - W_Deckenanschluss: Gleitender Deckenanschluss Fall 01
 | H2 Ebene +4/ Dachebene | WI-VS | 1406Wa 0000006042 | yes | Codetext | m² | Trockenbauarbeiten | Wand | Installationswand | WI-VS | 0 | A | 14.5 | 1263HWa0812769295 | NEW | no | no | 0 | 0 | no | 0 | no | Codetext | AllplanAttributes - W_Deckenanschluss: Gleitender Deckenanschluss Fall 01; ash_W_Trockenbau_Qualitäten: 3
 | H2 Ebene +4/ Dachebene | WI-STB | 1406Wa 0000006038 | yes | Codetext | m² | Betonarbeiten | Wand | Innenwand 1-Schalig | WI-STB | 0 | A | 14.5 | 1263HWa0812820345 | NEW | yes | no | REI 60-A1 - A2,s1-d0 / A1 | 0 | no | 42 | yes | Codetext
 | H2 Ebene +4/ Dachebene | WI-LB | 1406Wa 0000006009 | yes | Codetext | m² | Trockenbauarbeiten | Wand | Innenwand 1-Schalig | WI-LB | 0 | A | 14.5 | 1263HWa0812547284 | NEW | no | no | REI 30 | 0 | no | 42 | no | Codetext | AllplanAttributes - W_Deckenanschluss: Gleitender Deckenanschluss Fall 01; ash_W_Trockenbau_Qualitäten: 1b
 | H2 Ebene +4/ Dachebene | WI-LB | 1406Wa 0000004493 | yes | Codetext | m² | Trockenbauarbeiten | Wand | Innenwand 1-Schalig | WI-LB | 0 | A | 14.5 | 1263HWa0812547213 | NEW | no | no | REI 30 | 0 | no | 42 | no | Codetext | AllplanAttributes - W_Deckenanschluss: Gleitender Deckenanschluss Fall 01; ash_W_Trockenbau_Qualitäten: 1b
 | H2 Ebene +4/ Dachebene | Installationsraum | 1406Wa 0000004423 | yes | Codetext | m² | Trockenbauarbeiten | Wand | Installationswand | Installationsraum | 0 | A | 14.5 | 1263HWa0812593379 | NEW | no | no | 0 | 0 | no | 0 | no | Codetext | AllplanAttributes - W_Deckenanschluss: Gleitender Deckenanschluss Fall 01
 | H2 Ebene +4/ Dachebene | WI-VS | 1406Wa 0000004420 | yes | Codetext | m² | Trockenbauarbeiten | Wand | Installationswand | WI-VS | 0 | A | 14.5 | 1263HWa0812593379 | NEW | no | no | 0 | 0 | no | 0 | no | Codetext | AllplanAttributes - W_Deckenanschluss: Gleitender Deckenanschluss Fall 01; ash_W_Trockenbau_Qualitäten: 3
 | H2 Ebene +4/ Dachebene | WI-HW 60 | 1406Wa 0000004230 | yes | Codetext | m² | Trockenbauarbeiten | Wand | Innenwand 1-Schalig | WI-HW 60 | 0 | A | 14.5 | 1263HWa0812546789 | NEW | yes | no | REI 60-A1 - D,s2-d0 +A1 | 0 | no | 0 | no | Codetext | AllplanAttributes - ash D_Detailverweis: J1; ash D_Plannummer: D1651
 | H2 Ebene +4/ Dachebene | WI-LB | 1406Wa 0000004210 | yes | Codetext | m² | Trockenbauarbeiten | Wand | Innenwand 1-Schalig | WI-LB | 0 | A | 14.5 | 1263HWa0812545395 | NEW | no | no | REI 60-A1 - A2,s1-d0 / A1 | 0 | no | 0 | no | Codetext | AllplanAttributes - W_Deckenanschluss: Gleitender Deckenanschluss Fall 01; ash_W_Trockenbau_Qualitäten: 1b
 | H2 Ebene +4/ Dachebene | WI-LB | 1406Wa 0000004225 | yes | Codetext | m² | Trockenbauarbeiten | Wand | Innenwand 1-Schalig | WI-LB | 0 | A | 14.5 | 1263HWa0812545191 | NEW | no | no | REI 60-A1 - A2,s1-d0 / A1 | 0 | no | 0 | no | Codetext | AllplanAttributes - W_Deckenanschluss: Gleitender Deckenanschluss Fall 01; ash_W_Trockenbau_Qualitäten: 1b
 | H2 Ebene +4/ Dachebene | WI-STB | 1406Wa 0000004264 | yes | Codetext | m² | Betonarbeiten | Wand | Innenwand 1-Schalig | WI-STB | 0 | A | 14.5 | 1263HWa0812550766 | NEW | no | no | REI 60-A1 - A2,s1-d0 / A1 | 0 | no | 0 | no | Codetext
 | H2 Ebene +4/ Dachebene | WI-LB | 1406Wa 0000004260 | yes | Codetext | m² | Trockenbauarbeiten | Wand | Innenwand 1-Schalig | WI-LB | 0 | A | 14.5 | 1213HWa0812969822 | NEW | no | no | REI 60-A1 - D,s2-d0 /A1 | 0 | no | 0 | no | Codetext | AllplanAttributes - ash_W_Trockenbau_Qualitäten: 16
 | H2 Ebene +4/ Dachebene | WI-STB | 1406Wa 0000004251 | yes | Codetext | m² | Betonarbeiten | Wand | Innenwand 1-Schalig | WI-STB | 0 | A | 14.5 | 1263HWa0812544980 | NEW |  | no | REI 60-A1 - A2,s1-d0 / A1 | 0 | no | 0 | no | Codetext
 | H2 Ebene +4/ Dachebene | WI-LB | 1406Wa 0000004266 | yes | Codetext | m² | Trockenbauarbeiten | Wand | Innenwand 1-Schalig | WI-LB | 0 | A | 14.5 | 1263HWa0812544980 | NEW |  | no | REI 60-A1 - D,s2-d0 +A1 | 0 | no | 0 | no | Codetext | AllplanAttributes - ash_W_Trockenbau_Qualitäten: 9
 | H2 Ebene +4/ Dachebene | WI-STB | 1406Wa 0000013153 | yes | Codetext | m² | Betonarbeiten | Wand | Innenwand 1-Schalig | WI-STB | 0 | A | 14.5 | 1263HWa0812544980 | NEW |  | no | REI 60-A1 - A2,s1-d0 / A1 | 0 | no | 0 | no | Codetext
 | H2 Ebene +4/ Dachebene | WI-LB | 1406Wa 0000013154 | yes | Codetext | m² | Trockenbauarbeiten | Wand | Innenwand 1-Schalig | WI-LB | 0 | A | 14.5 | 1263HWa0812544980 | NEW |  | no | REI 60-A1 - D,s2-d0 +A1 | 0 | no | 0 | no | Codetext | AllplanAttributes - ash_W_Trockenbau_Qualitäten: 9
 | H2 Ebene +4/ Dachebene | WI-LB | 1406Wa 0000013288 | yes | Codetext | m² | Trockenbauarbeiten | Wand | Innenwand 1-Schalig | WI-LB | 0 | A | 14.5 | 1263HWa0812843014 | NEW | no | no | REI 30 | 0 | no | 42 | no | Codetext | AllplanAttributes - W_Deckenanschluss: Gleitender Deckenanschluss Fall 01; ash_W_Trockenbau_Qualitäten: 1b
 | H2 Ebene +4/ Dachebene | WI-LB | 1406Wa 0000004426 | yes | Codetext | m² | Trockenbauarbeiten | Wand | Innenwand 1-Schalig | WI-LB | 0 | A | 14.5 | 1263HWa0812843014 | NEW | no | no | REI 30 | 0 | no | 42 | no | Codetext | AllplanAttributes - W_Deckenanschluss: Gleitender Deckenanschluss Fall 01; ash_W_Trockenbau_Qualitäten: 1b
 | H2 Ebene +4/ Dachebene | WI-LB | 1406Wa 0000004412 | yes | Codetext | m² | Trockenbauarbeiten | Wand | Innenwand 1-Schalig | WI-LB | 0 | A | 14.5 | 1263HWa0812843014 | NEW | no | no | REI 30 | 0 | no | 42 | no | Codetext | AllplanAttributes - W_Deckenanschluss: Gleitender Deckenanschluss Fall 01; ash_W_Trockenbau_Qualitäten: 18
 | H2 Ebene +4/ Dachebene | WI-LB | 1406Wa 0000004499 | yes | Codetext | m² | Trockenbauarbeiten | Wand | Innenwand 1-Schalig | WI-LB | 0 | A | 14.5 | 1263HWa0812843014 | NEW | no | no | REI 30 | 0 | no | 42 | no | Codetext | AllplanAttributes - W_Deckenanschluss: Gleitender Deckenanschluss Fall 01; ash_W_Trockenbau_Qualitäten: 18
 | H2 Ebene +4/ Dachebene | WI-LB | 1406Wa 0000013425 | yes | Codetext | m² | Trockenbauarbeiten | Wand | Innenwand 1-Schalig | WI-LB | 0 | A | 14.5 | 1263HWa0812843014 | NEW | no | no | REI 30 | 0 | no | 42 | no | Codetext | AllplanAttributes - W_Deckenanschluss: Gleitender Deckenanschluss Fall 01; ash_W_Trockenbau_Qualitäten: 18
 | H2 Ebene +4/ Dachebene | WI-LB | 1406Wa 0000004490 | yes | Codetext | m² | Trockenbauarbeiten | Wand | Innenwand 1-Schalig | WI-LB | 0 | A | 14.5 | 1263HWa0812843014 | NEW | no | no | REI 30 | 0 | no | 42 | no | Codetext | AllplanAttributes - W_Deckenanschluss: Gleitender Deckenanschluss Fall 01; ash_W_Trockenbau_Qualitäten: 1b
 | H2 Ebene +4/ Dachebene | WI-LB | 1406Wa 0000004408 | yes | Codetext | m² | Trockenbauarbeiten | Wand | Innenwand 1-Schalig | WI-LB | 0 | A | 14.5 | 1263HWa0812843014 | NEW | no | no | REI 30 | 0 | no | 42 | no | Codetext | AllplanAttributes - W_Deckenanschluss: Gleitender Deckenanschluss Fall 01; ash_W_Trockenbau_Qualitäten: 1b
 | H2 Ebene +4/ Dachebene | WI-STB | 1406Wa 0000013186 | yes | Codetext | m² | Betonarbeiten | Wand | Innenwand 1-Schalig | WI-STB | 0 | A | 14.5 | 1263HWa0812544974 | NEW | no | no | REI 60-A1 - A2,s1-d0 / A1 | 0 | no | 0 | no | Codetext
 | H2 Ebene +4/ Dachebene | WI-STB | 1406Wa 0000013210 | yes | Codetext | m² | Betonarbeiten | Wand | Innenwand 1-Schalig | WI-STB | 0 | A | 14.5 | 1263HWa0812544976 | NEW | yes | no | REI 60-A1 - A2,s1-d0 / A1 | 0 | no | 0 | no | Codetext
 | H2 Ebene +4/ Dachebene | WI-STB | 1406Wa 0000004248 | yes | Codetext | m² | Betonarbeiten | Wand | Innenwand 1-Schalig | WI-STB | 0 | A | 14.5 | 1263HWa0812544974 | NEW | no | no | REI 60-A1 - A2,s1-d0 / A1 | 0 | no | 0 | no | Codetext
 | H2 Ebene +4/ Dachebene | WI-STB | 1406Wa 0000004273 | yes | Codetext | m² | Betonarbeiten | Wand | Innenwand 1-Schalig | WI-STB | 0 | A | 14.5 | 1263HWa0812550813 | NEW | yes | no | REI 60-A1 - A2,s1-d0 / A1 | 0 | no | 0 | no | Codetext
 | H2 Ebene +4/ Dachebene | WI-STB | 1406Wa 0000004238 | yes | Codetext | m² | Betonarbeiten | Wand | Innenwand 1-Schalig | WI-STB | 0 | A | 14.5 | 1263HWa0812544976 | NEW | yes | no | REI 60-A1 - A2,s1-d0 / A1 | 0 | no | 0 | no | Codetext
 | H2 Ebene +4/ Dachebene | WI-STB | 1406Wa 0000004242 | yes | Codetext | m² | Betonarbeiten | Wand | Innenwand 1-Schalig | WI-STB | 0 | A | 14.5 | 1263HWa0812786878 | NEW | yes | no | REI 60-A1 - A2,s1-d0 / A1 | 0 | no | 0 | no | Codetext
 | H2 Ebene +4/ Dachebene | WI-LB | 1406Wa 0000004245 | yes | Codetext | m² | Trockenbauarbeiten | Wand | Innenwand 1-Schalig | WI-LB | 0 | A | 14.5 | 1263HWa0812544490 | NEW |  | no | REI 60-A1 - D,s2-d0 +A1 | 0 | no | 0 | no | Codetext | AllplanAttributes - ash_W_Trockenbau_Qualitäten: 9
 | H2 Ebene +4/ Dachebene | WI-STB | 1406Wa 0000004270 | yes | Codetext | m² | Betonarbeiten | Wand | Innenwand 1-Schalig | WI-STB | 0 | A | 14.5 | 1263HWa0812544490 | NEW |  | no | REI 60-A1 - A2,s1-d0 / A1 | 0 | no | 0 | no | Codetext
 | H2 Ebene +4/ Dachebene | WI-LB | 1406Wa 0000004221 | yes | Codetext | m² | Trockenbauarbeiten | Wand | Innenwand 1-Schalig | WI-LB | 0 | A | 14.5 | 1263HWa0812545395 | NEW | no | no | REI 60-A1 - A2,s1-d0 / A1 | 0 | no | 0 | no | Codetext | AllplanAttributes - W_Deckenanschluss: Gleitender Deckenanschluss Fall 01; ash_W_Trockenbau_Qualitäten: 1b
 | H2 Ebene +4/ Dachebene | WI-LB | 1406Wa 0000003560 | yes | Codetext | m² | Trockenbauarbeiten | Wand |  | WI-LB | 0 | A | 14.5 | 1263HWa0812750832 | NEW | no | no | REI 60-A1 - A2,s1-d0 / A1 | 0 | no | 0 | no | Codetext
 | H2 Ebene +4/ Dachebene | WI-LB | 1406Wa 0000003556 | yes | Codetext | m² | Trockenbauarbeiten | Wand |  | WI-LB | 0 | A | 14.5 | 1263HWa0812750820 | NEW | no | no | REI 60-A1 - A2,s1-d0 / A1 | 0 | no | 0 | no | Codetext
 | H2 Ebene +4/ Dachebene | WI-LB | 1406Wa 0000003562 | yes | Codetext | m² | Trockenbauarbeiten | Wand |  | WI-LB | 0 | A | 14.5 | 1263HWa0812750837 | NEW | no | no | REI 60-A1 - A2,s1-d0 / A1 | 0 | no | 0 | no | Codetext
 | H2 Ebene +4/ Dachebene | WI-LB | 1406Wa 0000003558 | yes | Codetext | m² | Trockenbauarbeiten | Wand |  | WI-LB | 0 | A | 14.5 | 1263HWa0812750825 | NEW | no | no | REI 60-A1 - A2,s1-d0 / A1 | 0 | no | 0 | no | Codetext
 | H2 Ebene +4/ Dachebene | WI-LB | 1406Wa 0000005910 | yes | Codetext | m² | Trockenbauarbeiten | Wand |  | WI-LB | 0 | A | 14.5 | 1263HWa0812750832 | NEW | no | no | REI 60-A1 - A2,s1-d0 / A1 | 0 | no | 0 | no | Codetext
 | H2 Ebene +4/ Dachebene | WI-LB | 1406Wa 0000005908 | yes | Codetext | m² | Trockenbauarbeiten | Wand |  | WI-LB | 0 | A | 14.5 | 1263HWa0812750820 | NEW | no | no | REI 60-A1 - A2,s1-d0 / A1 | 0 | no | 0 | no | Codetext
 | H2 Ebene +4/ Dachebene | WI-LB | 1406Wa 0000005904 | yes | Codetext | m² | Trockenbauarbeiten | Wand |  | WI-LB | 0 | A | 14.5 | 1263HWa0812750825 | NEW | no | no | REI 60-A1 - A2,s1-d0 / A1 | 0 | no | 0 | no | Codetext
 | H2 Ebene +4/ Dachebene | WI-LB | 1406Wa 0000005906 | yes | Codetext | m² | Trockenbauarbeiten | Wand |  | WI-LB | 0 | A | 14.5 | 1263HWa0812750837 | NEW | no | no | REI 60-A1 - A2,s1-d0 / A1 | 0 | no | 0 | no | Codetext
 | H2 Ebene +4/ Dachebene | WI-HW 60 | 1406Wa 0000004461 | yes | Codetext | m² | Trockenbauarbeiten | Wand | Innenwand 1-Schalig | WI-HW 60 | 0 | A | 14.5 | 1263HWa0812824837 | NEW | yes | no | REI-M 60-D,s2,d0 + A1 | 0 | no | 42 | no | Codetext | AllplanAttributes - ash D_Detailverweis: DT 7; ash D_Plannummer: D1613
 | H2 Ebene +4/ Dachebene | WI-GKF | 1406Wa 0000006053 | yes | Codetext | m² | Trockenbauarbeiten | Wand | "BS-Beplankung; 2-fach Gipsfaserplatten" | WI-GKF | 0 | A | 14.5 | 1263HWa0812843382 | NEW | no | no |  | 0 | no | 0 | no | Codetext | AllplanAttributes - Ortscode_Geschoßbezeichnung: E04
 | H2 Ebene +4/ Dachebene | WI-GKF | 1406Wa 0000006055 | yes | Codetext | m² | Trockenbauarbeiten | Wand | "BS-Beplankung; 2-fach Gipsfaserplatten" | WI-GKF | 0 | A | 14.5 | 1263HWa0812800284 | NEW | no | no |  | 0 | no | 0 | no | Codetext | AllplanAttributes - Ortscode_Geschoßbezeichnung: E04
 | H2 Ebene +4/ Dachebene | WI-GKF | 1406Wa 0000006057 | yes | Codetext | m² | Trockenbauarbeiten | Wand | "BS-Beplankung; 2-fach Gipsfaserplatten" | WI-GKF | 0 | A | 14.5 | 1263HWa0812800285 | NEW | no | no |  | 0 | no | 0 | no | Codetext | AllplanAttributes - Ortscode_Geschoßbezeichnung: E04
 | H2 Ebene +4/ Dachebene | WI-LB | 1406Wa 0000003554 | yes | Codetext | m² | Trockenbauarbeiten | Wand | Innenwand 1-Schalig | WI-LB | 0 | A | 14.5 | 1263HWa0812544490 | NEW |  | no | REI 60-A1 - D,s2-d0 +A1 | 0 | no | 0 | no | Codetext | AllplanAttributes - Ortscode_Geschoßbezeichnung: E04; ash_W_Trockenbau_Qualitäten: 9
 | H2 Ebene +4/ Dachebene | WI-GKF | 1406Wa 0000006059 | yes | Codetext | m² | Trockenbauarbeiten | Wand | "BS-Beplankung; 2-fach Gipsfaserplatten" | WI-GKF | 0 | A | 14.5 | 1263HWa0812800283 | NEW | no | no |  | 0 | no | 0 | no | Codetext | AllplanAttributes - Ortscode_Geschoßbezeichnung: E04
 | H2 Ebene +4/ Dachebene | WI-STB | 1406Wa 0000004278 | yes | Codetext | m² | Betonarbeiten | Wand | Innenwand 1-Schalig | WI-STB | 0 | A | 14.5 | 1263HWa0812544977 | NEW | yes | no | REI 60-A1 - A2,s1-d0 / A1 | 0 | no | 0 | no | Codetext
 | H2 Ebene +4/ Dachebene | WI-LB | 1406Wa 0000004255 | yes | Codetext | m² | Trockenbauarbeiten | Wand | Innenwand 1-Schalig | WI-LB | 0 | A | 14.5 | 1213HWa0812969822 | NEW | no | no | REI 60-A1 - D,s2-d0 /A1 | 0 | no | 0 | no | Codetext | AllplanAttributes - ash_W_Trockenbau_Qualitäten: 16
 | H2 Ebene +4/ Dachebene | WI-STB | 1406Wa 0000016699 | yes | Codetext | m² | Betonarbeiten | Wand | Innenwand 1-Schalig | WI-STB | 0 | A | 14.5 | 1263HWa0812544977 | NEW | yes | no | REI 60-A1 - A2,s1-d0 / A1 | 0 | no | 0 | no | Codetext
 | H2 Ebene +4/ Dachebene | WI-LB | 1406Wa 0000016695 | yes | Codetext | m² | Trockenbauarbeiten | Wand | Innenwand 1-Schalig | WI-LB | 0 | A | 14.5 | 1213HWa0812969822 | NEW | no | no | REI 60-A1 - D,s2-d0 /A1 | 0 | no | 0 | no | Codetext | AllplanAttributes - ash_W_Trockenbau_Qualitäten: 16
 | H2 Ebene +4/ Dachebene | WI-LB | 1406Wa 0000003578 | yes | Codetext | m² | Trockenbauarbeiten | Wand | Innenwand 1-Schalig | WI-LB | 0 | A | 14.5 | 1263HWa0812845778 | NEW | no | no | REI 60-A1 - D,s2-d0 +A1 | 0 | no | 0 | no | Codetext
 | H2 Ebene +4/ Dachebene | WA-LB | 1407Wa 0000010122 | yes | Codetext | m² | Trockenbauarbeiten | Wand | Außenwand 7-Schalig | WA-LB | 0 | A | 11.25 | 1255HWa0000000069 | NEW | no | yes | 0 | 0 | no | 0 | no | Codetext
 | H2 Ebene +4/ Dachebene | WA-DL | 1407Wa 0000010124 | yes | Codetext | m³ | Zimmer- und Holzbauarbeiten | Wand | Außenwand 7-Schalig | WA-DL | 0 | A | 11.25 | 1255HWa0000000069 | NEW | no | yes | 0 | 0 | no | 0 | no | Codetext | AllplanAttributes - ash D_Detailverweis: DT D; ash D_Plannummer: D1851
 | H2 Ebene +4/ Dachebene | WA-DL | 1407Wa 0000010126 | yes | Codetext | m³ | Zimmer- und Holzbauarbeiten | Wand | Außenwand 7-Schalig | WA-DL | 0 | A | 11.25 | 1255HWa0000000069 | NEW | no | yes | 0 | 0 | no | 0 | no | Codetext
 | H2 Ebene +4/ Dachebene | WA-LB | 1407Wa 0000010128 | yes | Codetext | m² | Trockenbauarbeiten | Wand | Außenwand 7-Schalig | WA-LB | 0 | A | 11.25 | 1255HWa0000000069 | NEW | no | yes | 0 | 0 | no | 0 | no | Codetext
 | H2 Ebene +4/ Dachebene | WA-KL | 1407Wa 0000010130 | yes | Codetext | m² | Zimmer- und Holzbauarbeiten | Wand | Außenwand 7-Schalig | WA-KL | 0 | A | 11.25 | 1255HWa0000000069 | NEW | no | yes | 0 | 0 | no | 0 | no | Codetext
 | H2 Ebene +4/ Dachebene | WA-TL | 1407Wa 0000010132 | yes | Codetext | m² | Zimmer- und Holzbauarbeiten | Wand | Außenwand 7-Schalig | WA-TL | 0 | A | 11.25 | 1255HWa0000000069 | NEW | no | yes | 0 | 0 | no | 0 | no | Codetext
 | H2 Ebene +4/ Dachebene | WA-HS | 1407Wa 0000010134 | yes | Codetext | m² | Zimmer- und Holzbauarbeiten | Wand | Außenwand 7-Schalig | WA-HS | 0 | A | 11.25 | 1255HWa0000000069 | NEW | no | yes | 0 | 0 | no | 0 | no | Codetext
 | H2 Ebene +4/ Dachebene | WA-LB | 1407Wa 0000010092 | yes | Codetext | m² | Trockenbauarbeiten | Wand | Außenwand 7-Schalig | WA-LB | 0 | A | 11.25 | 1255HWa0000000069 | NEW | no | yes | 0 | 0 | no | 0 | no | Codetext
 | H2 Ebene +4/ Dachebene | WA-DL | 1407Wa 0000010094 | yes | Codetext | m³ | Zimmer- und Holzbauarbeiten | Wand | Außenwand 7-Schalig | WA-DL | 0 | A | 11.25 | 1255HWa0000000069 | NEW | no | yes | 0 | 0 | no | 0 | no | Codetext | AllplanAttributes - ash D_Detailverweis: DT D; ash D_Plannummer: D1851
 | H2 Ebene +4/ Dachebene | WA-DL | 1407Wa 0000010096 | yes | Codetext | m³ | Zimmer- und Holzbauarbeiten | Wand | Außenwand 7-Schalig | WA-DL | 0 | A | 11.25 | 1255HWa0000000069 | NEW | no | yes | 0 | 0 | no | 0 | no | Codetext
 | H2 Ebene +4/ Dachebene | WA-LB | 1407Wa 0000010098 | yes | Codetext | m² | Trockenbauarbeiten | Wand | Außenwand 7-Schalig | WA-LB | 0 | A | 11.25 | 1255HWa0000000069 | NEW | no | yes | 0 | 0 | no | 0 | no | Codetext
 | H2 Ebene +4/ Dachebene | WA-KL | 1407Wa 0000010100 | yes | Codetext | m² | Zimmer- und Holzbauarbeiten | Wand | Außenwand 7-Schalig | WA-KL | 0 | A | 11.25 | 1255HWa0000000069 | NEW | no | yes | 0 | 0 | no | 0 | no | Codetext
 | H2 Ebene +4/ Dachebene | WA-TL | 1407Wa 0000010102 | yes | Codetext | m² | Zimmer- und Holzbauarbeiten | Wand | Außenwand 7-Schalig | WA-TL | 0 | A | 11.25 | 1255HWa0000000069 | NEW | no | yes | 0 | 0 | no | 0 | no | Codetext
 | H2 Ebene +4/ Dachebene | WA-HS | 1407Wa 0000010104 | yes | Codetext | m² | Zimmer- und Holzbauarbeiten | Wand | Außenwand 7-Schalig | WA-HS | 0 | A | 11.25 | 1255HWa0000000069 | NEW | no | yes | 0 | 0 | no | 0 | no | Codetext
 | H2 Ebene +4/ Dachebene | WA-LB | 1407Wa 0000010266 | yes | Codetext | m² | Trockenbauarbeiten | Wand | Außenwand 7-Schalig | WA-LB | 0 | A | 11.25 | 1255HWa0811427521 | NEW | no | yes | 0 | 0 | no | 0 | no | Codetext
 | H2 Ebene +4/ Dachebene | WA-DL | 1407Wa 0000009956 | yes | Codetext | m³ | Zimmer- und Holzbauarbeiten | Wand | Außenwand 7-Schalig | WA-DL | 0 | A | 11.25 | 1255HWa0811427521 | NEW | no | yes | 0 | 0 | no | 0 | no | Codetext
 | H2 Ebene +4/ Dachebene | WA-DL | 1407Wa 0000009954 | yes | Codetext | m³ | Zimmer- und Holzbauarbeiten | Wand | Außenwand 7-Schalig | WA-DL | 0 | A | 11.25 | 1255HWa0811427521 | NEW | no | yes | 0 | 0 | no | 0 | no | Codetext
 | H2 Ebene +4/ Dachebene | WA-LB | 1407Wa 0000009952 | yes | Codetext | m² | Trockenbauarbeiten | Wand | Außenwand 7-Schalig | WA-LB | 0 | A | 11.25 | 1255HWa0811427521 | NEW | no | yes | 0 | 0 | no | 0 | no | Codetext
 | H2 Ebene +4/ Dachebene | WA-KL | 1407Wa 0000009950 | yes | Codetext | m² | Zimmer- und Holzbauarbeiten | Wand | Außenwand 7-Schalig | WA-KL | 0 | A | 11.25 | 1255HWa0811427521 | NEW | no | yes | 0 | 0 | no | 0 | no | Codetext
 | H2 Ebene +4/ Dachebene | WA-TL | 1407Wa 0000009948 | yes | Codetext | m² | Zimmer- und Holzbauarbeiten | Wand | Außenwand 7-Schalig | WA-TL | 0 | A | 11.25 | 1255HWa0811427521 | NEW | no | yes | 0 | 0 | no | 0 | no | Codetext
 | H2 Ebene +4/ Dachebene | WA-HS | 1407Wa 0000009946 | yes | Codetext | m² | Zimmer- und Holzbauarbeiten | Wand | Außenwand 7-Schalig | WA-HS | 0 | A | 11.25 | 1255HWa0811427521 | NEW | no | yes | 0 | 0 | no | 0 | no | Codetext
 | H2 Ebene +4/ Dachebene | WA-LB | 1407Wa 0000009932 | yes | Codetext | m² | Trockenbauarbeiten | Wand | Außenwand 7-Schalig | WA-LB | 0 | A | 11.25 | 1255HWa0811427521 | NEW | no | yes | 0 | 0 | no | 0 | no | Codetext
 | H2 Ebene +4/ Dachebene | WA-DL | 1407Wa 0000009934 | yes | Codetext | m³ | Zimmer- und Holzbauarbeiten | Wand | Außenwand 7-Schalig | WA-DL | 0 | A | 11.25 | 1255HWa0811427521 | NEW | no | yes | 0 | 0 | no | 0 | no | Codetext
 | H2 Ebene +4/ Dachebene | WA-DL | 1407Wa 0000009936 | yes | Codetext | m³ | Zimmer- und Holzbauarbeiten | Wand | Außenwand 7-Schalig | WA-DL | 0 | A | 11.25 | 1255HWa0811427521 | NEW | no | yes | 0 | 0 | no | 0 | no | Codetext
 | H2 Ebene +4/ Dachebene | WA-LB | 1407Wa 0000009938 | yes | Codetext | m² | Trockenbauarbeiten | Wand | Außenwand 7-Schalig | WA-LB | 0 | A | 11.25 | 1255HWa0811427521 | NEW | no | yes | 0 | 0 | no | 0 | no | Codetext
 | H2 Ebene +4/ Dachebene | WA-KL | 1407Wa 0000009940 | yes | Codetext | m² | Zimmer- und Holzbauarbeiten | Wand | Außenwand 7-Schalig | WA-KL | 0 | A | 11.25 | 1255HWa0811427521 | NEW | no | yes | 0 | 0 | no | 0 | no | Codetext
 | H2 Ebene +4/ Dachebene | WA-TL | 1407Wa 0000009942 | yes | Codetext | m² | Zimmer- und Holzbauarbeiten | Wand | Außenwand 7-Schalig | WA-TL | 0 | A | 11.25 | 1255HWa0811427521 | NEW | no | yes | 0 | 0 | no | 0 | no | Codetext
 | H2 Ebene +4/ Dachebene | WA-HS | 1407Wa 0000009944 | yes | Codetext | m² | Zimmer- und Holzbauarbeiten | Wand | Außenwand 7-Schalig | WA-HS | 0 | A | 11.25 | 1255HWa0811427521 | NEW | no | yes | 0 | 0 | no | 0 | no | Codetext
 | H2 Ebene +4/ Dachebene | WA-LB | 1407Wa 0000010436 | yes | Codetext | m² | Trockenbauarbeiten | Wand | Außenwand 7-Schalig | WA-LB | 0 | A | 11.25 | 1255HWa0000000076 | NEW | no | yes | 0 | 0 | no | 0 | no | Codetext
 | H2 Ebene +4/ Dachebene | WA-DL | 1407Wa 0000010438 | yes | Codetext | m³ | Zimmer- und Holzbauarbeiten | Wand | Außenwand 7-Schalig | WA-DL | 0 | A | 11.25 | 1255HWa0000000076 | NEW | no | yes | 0 | 0 | no | 0 | no | Codetext
 | H2 Ebene +4/ Dachebene | WA-DL | 1407Wa 0000010440 | yes | Codetext | m³ | Zimmer- und Holzbauarbeiten | Wand | Außenwand 7-Schalig | WA-DL | 0 | A | 11.25 | 1255HWa0000000076 | NEW | no | yes | 0 | 0 | no | 0 | no | Codetext
 | H2 Ebene +4/ Dachebene | WA-LB | 1407Wa 0000010442 | yes | Codetext | m² | Trockenbauarbeiten | Wand | Außenwand 7-Schalig | WA-LB | 0 | A | 11.25 | 1255HWa0000000076 | NEW | no | yes | 0 | 0 | no | 0 | no | Codetext
 | H2 Ebene +4/ Dachebene | WA-KL | 1407Wa 0000010444 | yes | Codetext | m² | Zimmer- und Holzbauarbeiten | Wand | Außenwand 7-Schalig | WA-KL | 0 | A | 11.25 | 1255HWa0000000076 | NEW | no | yes | 0 | 0 | no | 0 | no | Codetext
 | H2 Ebene +4/ Dachebene | WA-TL | 1407Wa 0000010446 | yes | Codetext | m² | Zimmer- und Holzbauarbeiten | Wand | Außenwand 7-Schalig | WA-TL | 0 | A | 11.25 | 1255HWa0000000076 | NEW | no | yes | 0 | 0 | no | 0 | no | Codetext
 | H2 Ebene +4/ Dachebene | WA-HS | 1407Wa 0000010448 | yes | Codetext | m² | Zimmer- und Holzbauarbeiten | Wand | Außenwand 7-Schalig | WA-HS | 0 | A | 11.25 | 1255HWa0000000076 | NEW | no | yes | 0 | 0 | no | 0 | no | Codetext
 | H2 Ebene +4/ Dachebene | WA-LB | 1407Wa 0000010278 | yes | Codetext | m² | Trockenbauarbeiten | Wand | Außenwand 7-Schalig | WA-LB | 0 | A | 11.25 | 1255HWa0000000192 | NEW | no | yes | 0 | 0 | no | 0 | no | Codetext
 | H2 Ebene +4/ Dachebene | WA-DL | 1407Wa 0000010280 | yes | Codetext | m³ | Zimmer- und Holzbauarbeiten | Wand | Außenwand 7-Schalig | WA-DL | 0 | A | 11.25 | 1255HWa0000000192 | NEW | no | yes | 0 | 0 | no | 0 | no | Codetext
 | H2 Ebene +4/ Dachebene | WA-DL | 1407Wa 0000010282 | yes | Codetext | m³ | Zimmer- und Holzbauarbeiten | Wand | Außenwand 7-Schalig | WA-DL | 0 | A | 11.25 | 1255HWa0000000192 | NEW | no | yes | 0 | 0 | no | 0 | no | Codetext
 | H2 Ebene +4/ Dachebene | WA-LB | 1407Wa 0000010284 | yes | Codetext | m² | Trockenbauarbeiten | Wand | Außenwand 7-Schalig | WA-LB | 0 | A | 11.25 | 1255HWa0000000192 | NEW | no | yes | 0 | 0 | no | 0 | no | Codetext
 | H2 Ebene +4/ Dachebene | WA-KL | 1407Wa 0000010286 | yes | Codetext | m² | Zimmer- und Holzbauarbeiten | Wand | Außenwand 7-Schalig | WA-KL | 0 | A | 11.25 | 1255HWa0000000192 | NEW | no | yes | 0 | 0 | no | 0 | no | Codetext
 | H2 Ebene +4/ Dachebene | WA-TL | 1407Wa 0000010274 | yes | Codetext | m² | Zimmer- und Holzbauarbeiten | Wand | Außenwand 7-Schalig | WA-TL | 0 | A | 11.25 | 1255HWa0000000192 | NEW | no | yes | 0 | 0 | no | 0 | no | Codetext
 | H2 Ebene +4/ Dachebene | WA-HS | 1407Wa 0000010276 | yes | Codetext | m² | Zimmer- und Holzbauarbeiten | Wand | Außenwand 7-Schalig | WA-HS | 0 | A | 11.25 | 1255HWa0000000192 | NEW | no | yes | 0 | 0 | no | 0 | no | Codetext
 | H2 Ebene +4/ Dachebene | WA-LB | 1407Wa 0000010005 | yes | Codetext | m² | Trockenbauarbeiten | Wand | Außenwand 7-Schalig | WA-LB | 0 | A | 11.25 | 1255HWa0811466406 | NEW | no | yes | REI 60-A1 - D,s2-d0 +A1 | 0 | no | 0 | no | Codetext
 | H2 Ebene +4/ Dachebene | WA-HD | 1407Wa 0000010003 | yes | Codetext | m³ | Zimmer- und Holzbauarbeiten | Wand | Außenwand 7-Schalig | WA-HD | 0 | A | 11.25 | 1255HWa0811466406 | NEW | yes | yes | REI 60-A1 - D,s2-d0 +A1 | 0 | no | 0 | no | Codetext
 | H2 Ebene +4/ Dachebene | WA-DL | 1407Wa 0000010001 | yes | Codetext | m³ | Zimmer- und Holzbauarbeiten | Wand | Außenwand 7-Schalig | WA-DL | 0 | A | 11.25 | 1255HWa0811466406 | NEW | no | yes | REI 60-A1 - D,s2-d0 +A1 | 0 | no | 0 | no | Codetext
 | H2 Ebene +4/ Dachebene | WA-LB | 1407Wa 0000009999 | yes | Codetext | m² | Trockenbauarbeiten | Wand | Außenwand 7-Schalig | WA-LB | 0 | A | 11.25 | 1255HWa0811456429 | NEW | no | yes | 0 | 0 | no | 0 | no | Codetext
 | H2 Ebene +4/ Dachebene | WA-KL | 1407Wa 0000009997 | yes | Codetext | m² | Zimmer- und Holzbauarbeiten | Wand | Außenwand 7-Schalig | WA-KL | 0 | A | 11.25 | 1255HWa0811466406 | NEW | no | yes | REI 60-A1 - D,s2-d0 +A1 | 0 | no | 0 | no | Codetext
 | H2 Ebene +4/ Dachebene | WA-TL | 1407Wa 0000009995 | yes | Codetext | m² | Zimmer- und Holzbauarbeiten | Wand | Außenwand 7-Schalig | WA-TL | 0 | A | 11.25 | 1255HWa0811466406 | NEW | no | yes | REI 60-A1 - D,s2-d0 +A1 | 0 | no | 0 | no | Codetext
 | H2 Ebene +4/ Dachebene | WA-HS | 1407Wa 0000009993 | yes | Codetext | m² | Zimmer- und Holzbauarbeiten | Wand | Außenwand 7-Schalig | WA-HS | 0 | A | 11.25 | 1255HWa0811466406 | NEW | no | yes | REI 60-A1 - D,s2-d0 +A1 | 0 | no | 0 | no | Codetext
 | H2 Ebene +4/ Dachebene | WA-LB | 1407Wa 0000009978 | yes | Codetext | m² | Trockenbauarbeiten | Wand | Außenwand 7-Schalig | WA-LB | 0 | A | 11.25 | 1255HWa0811466406 | NEW | no | yes | REI 60-A1 - D,s2-d0 +A1 | 0 | no | 0 | no | Codetext
 | H2 Ebene +4/ Dachebene | WA-HD | 1407Wa 0000009980 | yes | Codetext | m³ | Zimmer- und Holzbauarbeiten | Wand | Außenwand 7-Schalig | WA-HD | 0 | A | 11.25 | 1255HWa0811466406 | NEW | yes | yes | REI 60-A1 - D,s2-d0 +A1 | 0 | no | 0 | no | Codetext
 | H2 Ebene +4/ Dachebene | WA-DL | 1407Wa 0000009982 | yes | Codetext | m³ | Zimmer- und Holzbauarbeiten | Wand | Außenwand 7-Schalig | WA-DL | 0 | A | 11.25 | 1255HWa0811466406 | NEW | no | yes | REI 60-A1 - D,s2-d0 +A1 | 0 | no | 0 | no | Codetext
 | H2 Ebene +4/ Dachebene | WA-LB | 1407Wa 0000009984 | yes | Codetext | m² | Trockenbauarbeiten | Wand | Außenwand 7-Schalig | WA-LB | 0 | A | 11.25 | 1255HWa0811456429 | NEW | no | yes | 0 | 0 | no | 0 | no | Codetext
 | H2 Ebene +4/ Dachebene | WA-KL | 1407Wa 0000009986 | yes | Codetext | m² | Zimmer- und Holzbauarbeiten | Wand | Außenwand 7-Schalig | WA-KL | 0 | A | 11.25 | 1255HWa0811466406 | NEW | no | yes | REI 60-A1 - D,s2-d0 +A1 | 0 | no | 0 | no | Codetext
 | H2 Ebene +4/ Dachebene | WA-TL | 1407Wa 0000009988 | yes | Codetext | m² | Zimmer- und Holzbauarbeiten | Wand | Außenwand 7-Schalig | WA-TL | 0 | A | 11.25 | 1255HWa0811466406 | NEW | no | yes | REI 60-A1 - D,s2-d0 +A1 | 0 | no | 0 | no | Codetext
 | H2 Ebene +4/ Dachebene | WA-HS | 1407Wa 0000009990 | yes | Codetext | m² | Zimmer- und Holzbauarbeiten | Wand | Außenwand 7-Schalig | WA-HS | 0 | A | 11.25 | 1255HWa0811466406 | NEW | no | yes | REI 60-A1 - D,s2-d0 +A1 | 0 | no | 0 | no | Codetext
 | H2 Ebene +4/ Dachebene | WA-LB | 1407Wa 0000010026 | yes | Codetext | m² | Trockenbauarbeiten | Wand | Außenwand 7-Schalig | WA-LB | 0 | A | 11.25 | 1255HWa0811466406 | NEW | no | yes | REI 60-A1 - D,s2-d0 +A1 | 0 | no | 0 | no | Codetext
 | H2 Ebene +4/ Dachebene | WA-HD | 1407Wa 0000010028 | yes | Codetext | m³ | Zimmer- und Holzbauarbeiten | Wand | Außenwand 7-Schalig | WA-HD | 0 | A | 11.25 | 1255HWa0811466406 | NEW | yes | yes | REI 60-A1 - D,s2-d0 +A1 | 0 | no | 0 | no | Codetext
 | H2 Ebene +4/ Dachebene | WA-DL | 1407Wa 0000010030 | yes | Codetext | m³ | Zimmer- und Holzbauarbeiten | Wand | Außenwand 7-Schalig | WA-DL | 0 | A | 11.25 | 1255HWa0811466406 | NEW | no | yes | REI 60-A1 - D,s2-d0 +A1 | 0 | no | 0 | no | Codetext
 | H2 Ebene +4/ Dachebene | WA-LB | 1407Wa 0000010032 | yes | Codetext | m² | Trockenbauarbeiten | Wand | Außenwand 7-Schalig | WA-LB | 0 | A | 11.25 | 1255HWa0811456429 | NEW | no | yes | 0 | 0 | no | 0 | no | Codetext
 | H2 Ebene +4/ Dachebene | WA-KL | 1407Wa 0000010034 | yes | Codetext | m² | Zimmer- und Holzbauarbeiten | Wand | Außenwand 7-Schalig | WA-KL | 0 | A | 11.25 | 1255HWa0811466406 | NEW | no | yes | REI 60-A1 - D,s2-d0 +A1 | 0 | no | 0 | no | Codetext
 | H2 Ebene +4/ Dachebene | WA-TL | 1407Wa 0000010036 | yes | Codetext | m² | Zimmer- und Holzbauarbeiten | Wand | Außenwand 7-Schalig | WA-TL | 0 | A | 11.25 | 1255HWa0811466406 | NEW | no | yes | REI 60-A1 - D,s2-d0 +A1 | 0 | no | 0 | no | Codetext
 | H2 Ebene +4/ Dachebene | WA-HS | 1407Wa 0000010038 | yes | Codetext | m² | Zimmer- und Holzbauarbeiten | Wand | Außenwand 7-Schalig | WA-HS | 0 | A | 11.25 | 1255HWa0811466406 | NEW | no | yes | REI 60-A1 - D,s2-d0 +A1 | 0 | no | 0 | no | Codetext
 | H2 Ebene +4/ Dachebene | WA-LB | 1407Wa 0000010053 | yes | Codetext | m² | Trockenbauarbeiten | Wand | Außenwand 7-Schalig | WA-LB | 0 | A | 11.25 | 1255HWa0811466406 | NEW | no | yes | REI 60-A1 - D,s2-d0 +A1 | 0 | no | 0 | no | Codetext
 | H2 Ebene +4/ Dachebene | WA-HD | 1407Wa 0000010051 | yes | Codetext | m³ | Zimmer- und Holzbauarbeiten | Wand | Außenwand 7-Schalig | WA-HD | 0 | A | 11.25 | 1255HWa0811466406 | NEW | yes | yes | REI 60-A1 - D,s2-d0 +A1 | 0 | no | 0 | no | Codetext
 | H2 Ebene +4/ Dachebene | WA-DL | 1407Wa 0000010049 | yes | Codetext | m³ | Zimmer- und Holzbauarbeiten | Wand | Außenwand 7-Schalig | WA-DL | 0 | A | 11.25 | 1255HWa0811466406 | NEW | no | yes | REI 60-A1 - D,s2-d0 +A1 | 0 | no | 0 | no | Codetext
 | H2 Ebene +4/ Dachebene | WA-LB | 1407Wa 0000010047 | yes | Codetext | m² | Trockenbauarbeiten | Wand | Außenwand 7-Schalig | WA-LB | 0 | A | 11.25 | 1255HWa0811456429 | NEW | no | yes | 0 | 0 | no | 0 | no | Codetext
 | H2 Ebene +4/ Dachebene | WA-KL | 1407Wa 0000010045 | yes | Codetext | m² | Zimmer- und Holzbauarbeiten | Wand | Außenwand 7-Schalig | WA-KL | 0 | A | 11.25 | 1255HWa0811466406 | NEW | no | yes | REI 60-A1 - D,s2-d0 +A1 | 0 | no | 0 | no | Codetext
 | H2 Ebene +4/ Dachebene | WA-TL | 1407Wa 0000010043 | yes | Codetext | m² | Zimmer- und Holzbauarbeiten | Wand | Außenwand 7-Schalig | WA-TL | 0 | A | 11.25 | 1255HWa0811466406 | NEW | no | yes | REI 60-A1 - D,s2-d0 +A1 | 0 | no | 0 | no | Codetext
 | H2 Ebene +4/ Dachebene | WA-HS | 1407Wa 0000010041 | yes | Codetext | m² | Zimmer- und Holzbauarbeiten | Wand | Außenwand 7-Schalig | WA-HS | 0 | A | 11.25 | 1255HWa0811466406 | NEW | no | yes | REI 60-A1 - D,s2-d0 +A1 | 0 | no | 0 | no | Codetext
 | H2 Ebene +4/ Dachebene | WA-LB | 1407Wa 0000012640 | yes | Codetext | m² | Trockenbauarbeiten | Wand | Außenwand 7-Schalig | WA-LB | 0 | A | 11.25 | 1255HWa0811466406 | NEW | no | yes | REI 60-A1 - D,s2-d0 +A1 | 0 | no | 0 | no | Codetext
 | H2 Ebene +4/ Dachebene | WA-HD | 1407Wa 0000012641 | yes | Codetext | m³ | Zimmer- und Holzbauarbeiten | Wand | Außenwand 7-Schalig | WA-HD | 0 | A | 11.25 | 1255HWa0811466406 | NEW | yes | yes | REI 60-A1 - D,s2-d0 +A1 | 0 | no | 0 | no | Codetext
 | H2 Ebene +4/ Dachebene | WA-DL | 1407Wa 0000012642 | yes | Codetext | m³ | Zimmer- und Holzbauarbeiten | Wand | Außenwand 7-Schalig | WA-DL | 0 | A | 11.25 | 1255HWa0811466406 | NEW | no | yes | REI 60-A1 - D,s2-d0 +A1 | 0 | no | 0 | no | Codetext
 | H2 Ebene +4/ Dachebene | WA-LB | 1407Wa 0000012643 | yes | Codetext | m² | Trockenbauarbeiten | Wand | Außenwand 7-Schalig | WA-LB | 0 | A | 11.25 | 1255HWa0811456429 | NEW | no | yes | 0 | 0 | no | 0 | no | Codetext
 | H2 Ebene +4/ Dachebene | WA-KL | 1407Wa 0000012644 | yes | Codetext | m² | Zimmer- und Holzbauarbeiten | Wand | Außenwand 7-Schalig | WA-KL | 0 | A | 11.25 | 1255HWa0811466406 | NEW | no | yes | REI 60-A1 - D,s2-d0 +A1 | 0 | no | 0 | no | Codetext
 | H2 Ebene +4/ Dachebene | WA-TL | 1407Wa 0000012645 | yes | Codetext | m² | Zimmer- und Holzbauarbeiten | Wand | Außenwand 7-Schalig | WA-TL | 0 | A | 11.25 | 1255HWa0811466406 | NEW | no | yes | REI 60-A1 - D,s2-d0 +A1 | 0 | no | 0 | no | Codetext
 | H2 Ebene +4/ Dachebene | WA-HS | 1407Wa 0000012646 | yes | Codetext | m² | Zimmer- und Holzbauarbeiten | Wand | Außenwand 7-Schalig | WA-HS | 0 | A | 11.25 | 1255HWa0811466406 | NEW | no | yes | REI 60-A1 - D,s2-d0 +A1 | 0 | no | 0 | no | Codetext
 | H2 Ebene +4/ Dachebene | WA-LB | 1407Wa 0000010188 | yes | Codetext | m² | Trockenbauarbeiten | Wand | Außenwand 7-Schalig | WA-LB | 0 | A | 11.25 | 1255HWa0811466406 | NEW | no | yes | REI 60-A1 - D,s2-d0 +A1 | 0 | no | 0 | no | Codetext
 | H2 Ebene +4/ Dachebene | WA-HD | 1407Wa 0000010190 | yes | Codetext | m³ | Zimmer- und Holzbauarbeiten | Wand | Außenwand 7-Schalig | WA-HD | 0 | A | 11.25 | 1255HWa0811466406 | NEW | yes | yes | REI 60-A1 - D,s2-d0 +A1 | 0 | no | 0 | no | Codetext
 | H2 Ebene +4/ Dachebene | WA-DL | 1407Wa 0000010192 | yes | Codetext | m³ | Zimmer- und Holzbauarbeiten | Wand | Außenwand 7-Schalig | WA-DL | 0 | A | 11.25 | 1255HWa0811466406 | NEW | no | yes | REI 60-A1 - D,s2-d0 +A1 | 0 | no | 0 | no | Codetext
 | H2 Ebene +4/ Dachebene | WA-LB | 1407Wa 0000010194 | yes | Codetext | m² | Trockenbauarbeiten | Wand | Außenwand 7-Schalig | WA-LB | 0 | A | 11.25 | 1255HWa0811456429 | NEW | no | yes | 0 | 0 | no | 0 | no | Codetext
 | H2 Ebene +4/ Dachebene | WA-KL | 1407Wa 0000010196 | yes | Codetext | m² | Zimmer- und Holzbauarbeiten | Wand | Außenwand 7-Schalig | WA-KL | 0 | A | 11.25 | 1255HWa0811466406 | NEW | no | yes | REI 60-A1 - D,s2-d0 +A1 | 0 | no | 0 | no | Codetext
 | H2 Ebene +4/ Dachebene | WA-TL | 1407Wa 0000010198 | yes | Codetext | m² | Zimmer- und Holzbauarbeiten | Wand | Außenwand 7-Schalig | WA-TL | 0 | A | 11.25 | 1255HWa0811466406 | NEW | no | yes | REI 60-A1 - D,s2-d0 +A1 | 0 | no | 0 | no | Codetext
 | H2 Ebene +4/ Dachebene | WA-HS | 1407Wa 0000010200 | yes | Codetext | m² | Zimmer- und Holzbauarbeiten | Wand | Außenwand 7-Schalig | WA-HS | 0 | A | 11.25 | 1255HWa0811466406 | NEW | no | yes | REI 60-A1 - D,s2-d0 +A1 | 0 | no | 0 | no | Codetext
 | H2 Ebene +4/ Dachebene | WA-LB | 1407Wa 0000010167 | yes | Codetext | m² | Trockenbauarbeiten | Wand | Außenwand 7-Schalig | WA-LB | 0 | A | 11.25 | 1255HWa0811466406 | NEW | no | yes | REI 60-A1 - D,s2-d0 +A1 | 0 | no | 0 | no | Codetext
 | H2 Ebene +4/ Dachebene | WA-HD | 1407Wa 0000010165 | yes | Codetext | m³ | Zimmer- und Holzbauarbeiten | Wand | Außenwand 7-Schalig | WA-HD | 0 | A | 11.25 | 1255HWa0811466406 | NEW | yes | yes | REI 60-A1 - D,s2-d0 +A1 | 0 | no | 0 | no | Codetext
 | H2 Ebene +4/ Dachebene | WA-DL | 1407Wa 0000010163 | yes | Codetext | m³ | Zimmer- und Holzbauarbeiten | Wand | Außenwand 7-Schalig | WA-DL | 0 | A | 11.25 | 1255HWa0811466406 | NEW | no | yes | REI 60-A1 - D,s2-d0 +A1 | 0 | no | 0 | no | Codetext
 | H2 Ebene +4/ Dachebene | WA-LB | 1407Wa 0000010161 | yes | Codetext | m² | Trockenbauarbeiten | Wand | Außenwand 7-Schalig | WA-LB | 0 | A | 11.25 | 1255HWa0811456429 | NEW | no | yes | 0 | 0 | no | 0 | no | Codetext
 | H2 Ebene +4/ Dachebene | WA-KL | 1407Wa 0000010159 | yes | Codetext | m² | Zimmer- und Holzbauarbeiten | Wand | Außenwand 7-Schalig | WA-KL | 0 | A | 11.25 | 1255HWa0811466406 | NEW | no | yes | REI 60-A1 - D,s2-d0 +A1 | 0 | no | 0 | no | Codetext
 | H2 Ebene +4/ Dachebene | WA-TL | 1407Wa 0000010157 | yes | Codetext | m² | Zimmer- und Holzbauarbeiten | Wand | Außenwand 7-Schalig | WA-TL | 0 | A | 11.25 | 1255HWa0811466406 | NEW | no | yes | REI 60-A1 - D,s2-d0 +A1 | 0 | no | 0 | no | Codetext
 | H2 Ebene +4/ Dachebene | WA-HS | 1407Wa 0000010155 | yes | Codetext | m² | Zimmer- und Holzbauarbeiten | Wand | Außenwand 7-Schalig | WA-HS | 0 | A | 11.25 | 1255HWa0811466406 | NEW | no | yes | REI 60-A1 - D,s2-d0 +A1 | 0 | no | 0 | no | Codetext
 | H2 Ebene +4/ Dachebene | WA-LB | 1407Wa 0000010152 | yes | Codetext | m² | Trockenbauarbeiten | Wand | Außenwand 7-Schalig | WA-LB | 0 | A | 11.25 | 1255HWa0811466406 | NEW | no | yes | REI 60-A1 - D,s2-d0 +A1 | 0 | no | 0 | no | Codetext
 | H2 Ebene +4/ Dachebene | WA-HD | 1407Wa 0000010150 | yes | Codetext | m³ | Zimmer- und Holzbauarbeiten | Wand | Außenwand 7-Schalig | WA-HD | 0 | A | 11.25 | 1255HWa0811466406 | NEW | yes | yes | REI 60-A1 - D,s2-d0 +A1 | 0 | no | 0 | no | Codetext
 | H2 Ebene +4/ Dachebene | WA-DL | 1407Wa 0000010148 | yes | Codetext | m³ | Zimmer- und Holzbauarbeiten | Wand | Außenwand 7-Schalig | WA-DL | 0 | A | 11.25 | 1255HWa0811466406 | NEW | no | yes | REI 60-A1 - D,s2-d0 +A1 | 0 | no | 0 | no | Codetext
 | H2 Ebene +4/ Dachebene | WA-LB | 1407Wa 0000010146 | yes | Codetext | m² | Trockenbauarbeiten | Wand | Außenwand 7-Schalig | WA-LB | 0 | A | 11.25 | 1255HWa0811456429 | NEW | no | yes | 0 | 0 | no | 0 | no | Codetext
 | H2 Ebene +4/ Dachebene | WA-KL | 1407Wa 0000010144 | yes | Codetext | m² | Zimmer- und Holzbauarbeiten | Wand | Außenwand 7-Schalig | WA-KL | 0 | A | 11.25 | 1255HWa0811466406 | NEW | no | yes | REI 60-A1 - D,s2-d0 +A1 | 0 | no | 0 | no | Codetext
 | H2 Ebene +4/ Dachebene | WA-TL | 1407Wa 0000010142 | yes | Codetext | m² | Zimmer- und Holzbauarbeiten | Wand | Außenwand 7-Schalig | WA-TL | 0 | A | 11.25 | 1255HWa0811466406 | NEW | no | yes | REI 60-A1 - D,s2-d0 +A1 | 0 | no | 0 | no | Codetext
 | H2 Ebene +4/ Dachebene | WA-HS | 1407Wa 0000010140 | yes | Codetext | m² | Zimmer- und Holzbauarbeiten | Wand | Außenwand 7-Schalig | WA-HS | 0 | A | 11.25 | 1255HWa0811466406 | NEW | no | yes | REI 60-A1 - D,s2-d0 +A1 | 0 | no | 0 | no | Codetext
2x Gipsfaserplatte | H2 Ebene +4/ Dachebene | WA-LB | 1407Wa 0000010070 | yes |  | m² | Trockenbauarbeiten | Wand | 2x Gipsfaserplatte | WA-LB |  |  | 11.25 | 1255HWa0811456284 | NEW | no | yes | REI 60-A1 - D,s2-d0 +A1
2x Gipsfaserplatte | H2 Ebene +4/ Dachebene | WA-LB | 1407Wa 0000010072 | yes |  | m² | Trockenbauarbeiten | Wand | 2x Gipsfaserplatte | WA-LB |  |  | 11.25 | 1255HWa0811456284 | NEW | no | yes | 0 | 0.9 |  | 32 | AllplanAttributes - Sicherheitsklasse: -; Sonnenschutztyp: Movable; g-Wert: 0,51
Holzständer + Zwischendämmung | H2 Ebene +4/ Dachebene | WA-HD | 1407Wa 0000010074 | yes |  | m³ | Zimmer- und Holzbauarbeiten | Wand | Holzständer + Zwischendämmung | WA-HD |  |  | 11.25 | 1255HWa0811456284 | NEW | no | yes | REI 60-A1 - D,s2-d0 +A1 | AllplanAttributes - ash D_Detailverweis: DT A; ash D_Plannummer: D1850
 | H2 Ebene +4/ Dachebene | WA-LB | 1407Wa 0000010077 | yes | Codetext | m² | Trockenbauarbeiten | Wand | Außenwand 7-Schalig | WA-LB | 0 | A | 11.25 | 1255HWa0811456284 | NEW | no | yes | 0 | 0.9 | no | 32 | no | Codetext | AllplanAttributes - Sicherheitsklasse: -; Sonnenschutztyp: Movable; g-Wert: 0,51
 | H2 Ebene +4/ Dachebene | WA-LB | 1407Wa 0000010079 | yes | Codetext | m² | Trockenbauarbeiten | Wand | Außenwand 7-Schalig | WA-LB | 0 | A | 11.25 | 1255HWa0811456284 | NEW | no | yes | 0 | 0 | no | 0 | no | Codetext
Staffel + Zwischendämmung | H2 Ebene +4/ Dachebene | WA-DL | 1407Wa 0000010081 | yes |  | m³ | Zimmer- und Holzbauarbeiten | Wand | Staffel + Zwischendämmung | WA-DL |  |  | 11.25 | 1255HWa0811456284 | NEW | no | yes | REI 60-A1 - D,s2-d0 +A1
Konterlattung | H2 Ebene +4/ Dachebene | WA-KL | 1407Wa 0000010083 | yes |  | m² | Zimmer- und Holzbauarbeiten | Wand | Konterlattung | WA-KL |  |  | 11.25 | 1255HWa0811456284 | NEW | no | yes | REI 60-A1 - D,s2-d0 +A1
Traglattung | H2 Ebene +4/ Dachebene | WA-TL | 1407Wa 0000010085 | yes |  | m² | Zimmer- und Holzbauarbeiten | Wand | Traglattung | WA-TL |  |  | 11.25 | 1255HWa0811456284 | NEW | no | yes | REI 60-A1 - D,s2-d0 +A1
Holzschindel | H2 Ebene +4/ Dachebene | WA-HS | 1407Wa 0000010087 | yes |  | m² | Zimmer- und Holzbauarbeiten | Wand | Holzschindel | WA-HS |  |  | 11.25 | 1255HWa0811456284 | NEW | no | yes | REI 60-A1 - D,s2-d0 +A1 | AllplanAttributes - ash D_Detailverweis: DT 4; ash D_Plannummer: D1615
 | H2 Ebene +4/ Dachebene | WA-LB | 1407Wa 0000010108 | yes | Codetext | m² | Trockenbauarbeiten | Wand | Außenwand 7-Schalig | WA-LB | 0 | A | 11.25 | 1255HWa0000000069 | NEW | no | yes | 0 | 0 | no | 0 | no | Codetext
 | H2 Ebene +4/ Dachebene | WA-DL | 1407Wa 0000010110 | yes | Codetext | m³ | Zimmer- und Holzbauarbeiten | Wand | Außenwand 7-Schalig | WA-DL | 0 | A | 11.25 | 1255HWa0000000069 | NEW | no | yes | 0 | 0 | no | 0 | no | Codetext | AllplanAttributes - ash D_Detailverweis: DT D; ash D_Plannummer: D1851
 | H2 Ebene +4/ Dachebene | WA-DL | 1407Wa 0000010112 | yes | Codetext | m³ | Zimmer- und Holzbauarbeiten | Wand | Außenwand 7-Schalig | WA-DL | 0 | A | 11.25 | 1255HWa0000000069 | NEW | no | yes | 0 | 0 | no | 0 | no | Codetext
 | H2 Ebene +4/ Dachebene | WA-LB | 1407Wa 0000010114 | yes | Codetext | m² | Trockenbauarbeiten | Wand | Außenwand 7-Schalig | WA-LB | 0 | A | 11.25 | 1255HWa0000000069 | NEW | no | yes | 0 | 0 | no | 0 | no | Codetext
 | H2 Ebene +4/ Dachebene | WA-KL | 1407Wa 0000010116 | yes | Codetext | m² | Zimmer- und Holzbauarbeiten | Wand | Außenwand 7-Schalig | WA-KL | 0 | A | 11.25 | 1255HWa0000000069 | NEW | no | yes | 0 | 0 | no | 0 | no | Codetext
 | H2 Ebene +4/ Dachebene | WA-TL | 1407Wa 0000010118 | yes | Codetext | m² | Zimmer- und Holzbauarbeiten | Wand | Außenwand 7-Schalig | WA-TL | 0 | A | 11.25 | 1255HWa0000000069 | NEW | no | yes | 0 | 0 | no | 0 | no | Codetext
 | H2 Ebene +4/ Dachebene | WA-HS | 1407Wa 0000010120 | yes | Codetext | m² | Zimmer- und Holzbauarbeiten | Wand | Außenwand 7-Schalig | WA-HS | 0 | A | 11.25 | 1255HWa0000000069 | NEW | no | yes | 0 | 0 | no | 0 | no | Codetext
 | H2 Ebene +4/ Dachebene | WA-LB | 1407Wa 0000012223 | yes | Codetext | m² | Trockenbauarbeiten | Wand | Außenwand 7-Schalig | WA-LB | 0 | A | 11.25 | 1255HWa0811466406 | NEW | no | yes | REI 60-A1 - D,s2-d0 +A1 | 0 | no | 0 | no | Codetext
 | H2 Ebene +4/ Dachebene | WA-HD | 1407Wa 0000012224 | yes | Codetext | m³ | Zimmer- und Holzbauarbeiten | Wand | Außenwand 7-Schalig | WA-HD | 0 | A | 11.25 | 1255HWa0811466406 | NEW | yes | yes | REI 60-A1 - D,s2-d0 +A1 | 0 | no | 0 | no | Codetext
 | H2 Ebene +4/ Dachebene | WA-DL | 1407Wa 0000012225 | yes | Codetext | m³ | Zimmer- und Holzbauarbeiten | Wand | Außenwand 7-Schalig | WA-DL | 0 | A | 11.25 | 1255HWa0811466406 | NEW | no | yes | REI 60-A1 - D,s2-d0 +A1 | 0 | no | 0 | no | Codetext
 | H2 Ebene +4/ Dachebene | WA-LB | 1407Wa 0000012226 | yes | Codetext | m² | Trockenbauarbeiten | Wand | Außenwand 7-Schalig | WA-LB | 0 | A | 11.25 | 1255HWa0811456429 | NEW | no | yes | 0 | 0 | no | 0 | no | Codetext
 | H2 Ebene +4/ Dachebene | WA-KL | 1407Wa 0000012227 | yes | Codetext | m² | Zimmer- und Holzbauarbeiten | Wand | Außenwand 7-Schalig | WA-KL | 0 | A | 11.25 | 1255HWa0811466406 | NEW | no | yes | REI 60-A1 - D,s2-d0 +A1 | 0 | no | 0 | no | Codetext
 | H2 Ebene +4/ Dachebene | WA-TL | 1407Wa 0000012228 | yes | Codetext | m² | Zimmer- und Holzbauarbeiten | Wand | Außenwand 7-Schalig | WA-TL | 0 | A | 11.25 | 1255HWa0811466406 | NEW | no | yes | REI 60-A1 - D,s2-d0 +A1 | 0 | no | 0 | no | Codetext
 | H2 Ebene +4/ Dachebene | WA-HS | 1407Wa 0000012229 | yes | Codetext | m² | Zimmer- und Holzbauarbeiten | Wand | Außenwand 7-Schalig | WA-HS | 0 | A | 11.25 | 1255HWa0811466406 | NEW | no | yes | REI 60-A1 - D,s2-d0 +A1 | 0 | no | 0 | no | Codetext
2x Gipsfaserplatte | H2 Ebene +4/ Dachebene | WA-LB | 1407Wa 0000010248 | yes |  | m² | Trockenbauarbeiten | Wand | 2x Gipsfaserplatte | WA-LB |  |  | 11.25 | 1255HWa0811453583 | NEW | no | yes | REI 60-A1 - D,s2-d0 +A1
2x Gipsfaserplatte | H2 Ebene +4/ Dachebene | WA-LB | 1407Wa 0000010250 | yes |  | m² | Trockenbauarbeiten | Wand | 2x Gipsfaserplatte | WA-LB |  |  | 11.25 | 1255HWa0811453583 | NEW | no | yes | 0 | 0.9 |  | 32 | AllplanAttributes - Sicherheitsklasse: -; Sonnenschutztyp: Movable; g-Wert: 0,51
Holzständer + Zwischendämmung | H2 Ebene +4/ Dachebene | WA-HD | 1407Wa 0000010245 | yes |  | m³ | Zimmer- und Holzbauarbeiten | Wand | Holzständer + Zwischendämmung | WA-HD |  |  | 11.25 | 1255HWa0811453583 | NEW | no | yes | REI 60-A1 - D,s2-d0 +A1 | AllplanAttributes - ash D_Detailverweis: DT A; ash D_Plannummer: D1850
 | H2 Ebene +4/ Dachebene | WA-LB | 1407Wa 0000010243 | yes | Codetext | m² | Trockenbauarbeiten | Wand | Außenwand 7-Schalig | WA-LB | 0 | A | 11.25 | 1255HWa0811453583 | NEW | no | yes | 0 | 0.9 | no | 32 | no | Codetext | AllplanAttributes - Sicherheitsklasse: -; Sonnenschutztyp: Movable; g-Wert: 0,51
 | H2 Ebene +4/ Dachebene | WA-LB | 1407Wa 0000010241 | yes | Codetext | m² | Trockenbauarbeiten | Wand | Außenwand 7-Schalig | WA-LB | 0 | A | 11.25 | 1255HWa0811453583 | NEW | no | yes | 0 | 0 | no | 0 | no | Codetext
Staffel + Zwischendämmung | H2 Ebene +4/ Dachebene | WA-DL | 1407Wa 0000010239 | yes |  | m³ | Zimmer- und Holzbauarbeiten | Wand | Staffel + Zwischendämmung | WA-DL |  |  | 11.25 | 1255HWa0811453583 | NEW | no | yes | REI 60-A1 - D,s2-d0 +A1
Konterlattung | H2 Ebene +4/ Dachebene | WA-KL | 1407Wa 0000010237 | yes |  | m² | Zimmer- und Holzbauarbeiten | Wand | Konterlattung | WA-KL |  |  | 11.25 | 1255HWa0811453583 | NEW | no | yes | REI 60-A1 - D,s2-d0 +A1
Traglattung | H2 Ebene +4/ Dachebene | WA-TL | 1407Wa 0000010235 | yes |  | m² | Zimmer- und Holzbauarbeiten | Wand | Traglattung | WA-TL |  |  | 11.25 | 1255HWa0811453583 | NEW | no | yes | REI 60-A1 - D,s2-d0 +A1
Holzschindel | H2 Ebene +4/ Dachebene | WA-HS | 1407Wa 0000010232 | yes |  | m² | Zimmer- und Holzbauarbeiten | Wand | Holzschindel | WA-HS |  |  | 11.25 | 1255HWa0811453583 | NEW | no | yes | REI 60-A1 - D,s2-d0 +A1 | AllplanAttributes - ash D_Detailverweis: DT 4; ash D_Plannummer: D1615
 | H2 Ebene +4/ Dachebene | WA-LB | 1407Wa 0000010264 | yes | Codetext | m² | Trockenbauarbeiten | Wand | Außenwand 7-Schalig | WA-LB | 0 | A | 11.25 | 1255HWa0000000069 | NEW | no | yes | 0 | 0 | no | 0 | no | Codetext
 | H2 Ebene +4/ Dachebene | WA-DL | 1407Wa 0000010262 | yes | Codetext | m³ | Zimmer- und Holzbauarbeiten | Wand | Außenwand 7-Schalig | WA-DL | 0 | A | 11.25 | 1255HWa0000000069 | NEW | no | yes | 0 | 0 | no | 0 | no | Codetext | AllplanAttributes - ash D_Detailverweis: DT D; ash D_Plannummer: D1851
 | H2 Ebene +4/ Dachebene | WA-DL | 1407Wa 0000010260 | yes | Codetext | m³ | Zimmer- und Holzbauarbeiten | Wand | Außenwand 7-Schalig | WA-DL | 0 | A | 11.25 | 1255HWa0000000069 | NEW | no | yes | 0 | 0 | no | 0 | no | Codetext
 | H2 Ebene +4/ Dachebene | WA-LB | 1407Wa 0000010258 | yes | Codetext | m² | Trockenbauarbeiten | Wand | Außenwand 7-Schalig | WA-LB | 0 | A | 11.25 | 1255HWa0000000069 | NEW | no | yes | 0 | 0 | no | 0 | no | Codetext
 | H2 Ebene +4/ Dachebene | WA-KL | 1407Wa 0000010256 | yes | Codetext | m² | Zimmer- und Holzbauarbeiten | Wand | Außenwand 7-Schalig | WA-KL | 0 | A | 11.25 | 1255HWa0000000069 | NEW | no | yes | 0 | 0 | no | 0 | no | Codetext
 | H2 Ebene +4/ Dachebene | WA-TL | 1407Wa 0000010254 | yes | Codetext | m² | Zimmer- und Holzbauarbeiten | Wand | Außenwand 7-Schalig | WA-TL | 0 | A | 11.25 | 1255HWa0000000069 | NEW | no | yes | 0 | 0 | no | 0 | no | Codetext
 | H2 Ebene +4/ Dachebene | WA-HS | 1407Wa 0000010252 | yes | Codetext | m² | Zimmer- und Holzbauarbeiten | Wand | Außenwand 7-Schalig | WA-HS | 0 | A | 11.25 | 1255HWa0000000069 | NEW | no | yes | 0 | 0 | no | 0 | no | Codetext
 | H2 Ebene +4/ Dachebene | WA-LB | 1407Wa 0000010202 | yes | Codetext | m² | Trockenbauarbeiten | Wand | Außenwand 7-Schalig | WA-LB | 0 | A | 11.25 | 1255HWa0811466406 | NEW | no | yes | REI 60-A1 - D,s2-d0 +A1 | 0 | no | 0 | no | Codetext
 | H2 Ebene +4/ Dachebene | WA-HD | 1407Wa 0000010204 | yes | Codetext | m³ | Zimmer- und Holzbauarbeiten | Wand | Außenwand 7-Schalig | WA-HD | 0 | A | 11.25 | 1255HWa0811466406 | NEW | yes | yes | REI 60-A1 - D,s2-d0 +A1 | 0 | no | 0 | no | Codetext
 | H2 Ebene +4/ Dachebene | WA-DL | 1407Wa 0000010206 | yes | Codetext | m³ | Zimmer- und Holzbauarbeiten | Wand | Außenwand 7-Schalig | WA-DL | 0 | A | 11.25 | 1255HWa0811466406 | NEW | no | yes | REI 60-A1 - D,s2-d0 +A1 | 0 | no | 0 | no | Codetext
 | H2 Ebene +4/ Dachebene | WA-LB | 1407Wa 0000010208 | yes | Codetext | m² | Trockenbauarbeiten | Wand | Außenwand 7-Schalig | WA-LB | 0 | A | 11.25 | 1255HWa0811456429 | NEW | no | yes | 0 | 0 | no | 0 | no | Codetext
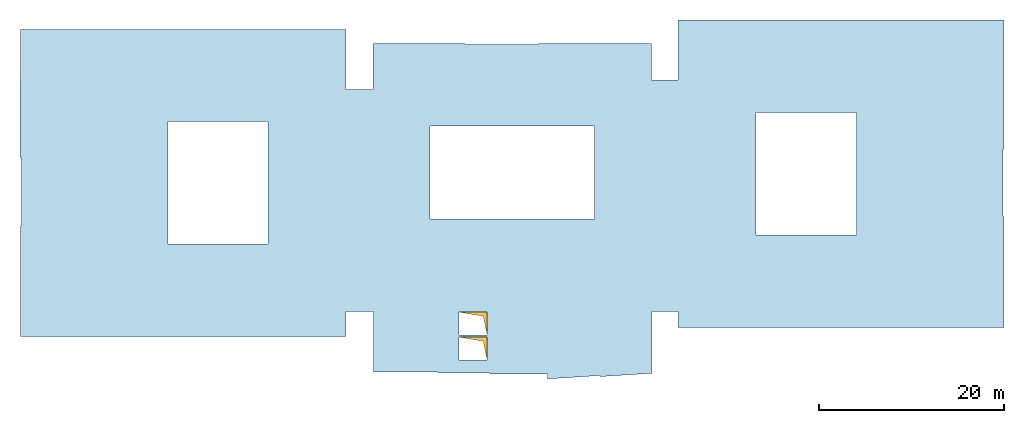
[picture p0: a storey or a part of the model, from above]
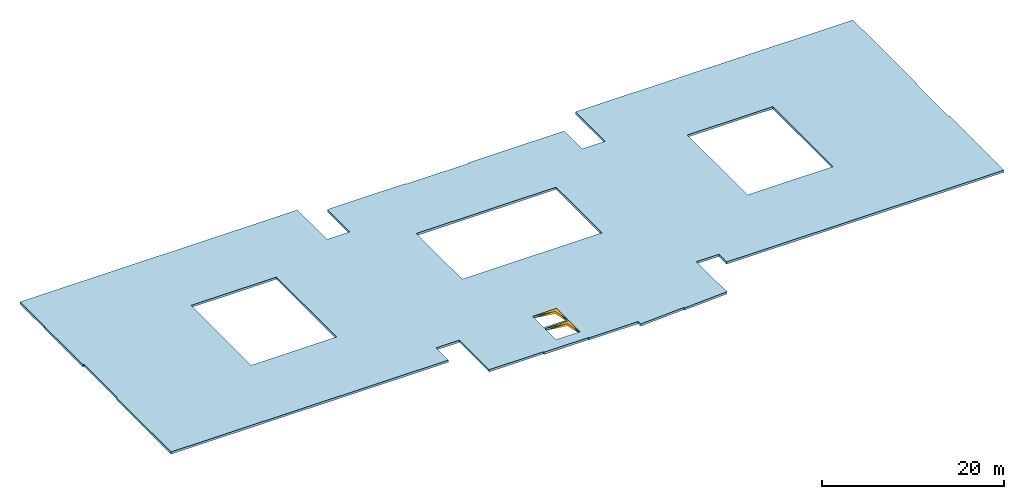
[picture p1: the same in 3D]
Properties of the parts of a building model (IFC4), part 45 of 80

# IfcWall (6826)
Name | In | Material | Allright_Bauteil_ID | 2D Interaktion | Codetext | Abrechnungsart | Gewerk | Objektname | Bezeichnung | AllplanAttributes, Material | Typ = SurfaceSpreadOfFlame | Brandschutzklasse | OKFF | P_ID | Status | LoadBearing | IsExternal | FireRating | ThermalTransmittance (W/K/m2) | Combustible | AcousticRating | Compartmentation | Reference
 | H2 Ebene +4/ Dachebene | WA-KL | 1407Wa 0000010210 | yes | Codetext | m² | Zimmer- und Holzbauarbeiten | Wand | Außenwand 7-Schalig | WA-KL | 0 | A | 11.25 | 1255HWa0811466406 | NEW | no | yes | REI 60-A1 - D,s2-d0 +A1 | 0 | no | 0 | no | Codetext
 | H2 Ebene +4/ Dachebene | WA-TL | 1407Wa 0000010212 | yes | Codetext | m² | Zimmer- und Holzbauarbeiten | Wand | Außenwand 7-Schalig | WA-TL | 0 | A | 11.25 | 1255HWa0811466406 | NEW | no | yes | REI 60-A1 - D,s2-d0 +A1 | 0 | no | 0 | no | Codetext
 | H2 Ebene +4/ Dachebene | WA-HS | 1407Wa 0000010214 | yes | Codetext | m² | Zimmer- und Holzbauarbeiten | Wand | Außenwand 7-Schalig | WA-HS | 0 | A | 11.25 | 1255HWa0811466406 | NEW | no | yes | REI 60-A1 - D,s2-d0 +A1 | 0 | no | 0 | no | Codetext
 | H2 Ebene +4/ Dachebene | WA-LB | 1407Wa 0000009968 | yes | Codetext | m² | Trockenbauarbeiten | Wand | Außenwand 7-Schalig | WA-LB | 0 | A | 11.25 | 1255HWa0000000069 | NEW | no | yes | 0 | 0 | no | 0 | no | Codetext
 | H2 Ebene +4/ Dachebene | WA-DL | 1407Wa 0000009966 | yes | Codetext | m³ | Zimmer- und Holzbauarbeiten | Wand | Außenwand 7-Schalig | WA-DL | 0 | A | 11.25 | 1255HWa0000000069 | NEW | no | yes | 0 | 0 | no | 0 | no | Codetext | AllplanAttributes - ash D_Detailverweis: DT D; ash D_Plannummer: D1851
 | H2 Ebene +4/ Dachebene | WA-DL | 1407Wa 0000009964 | yes | Codetext | m³ | Zimmer- und Holzbauarbeiten | Wand | Außenwand 7-Schalig | WA-DL | 0 | A | 11.25 | 1255HWa0000000069 | NEW | no | yes | 0 | 0 | no | 0 | no | Codetext
 | H2 Ebene +4/ Dachebene | WA-LB | 1407Wa 0000009962 | yes | Codetext | m² | Trockenbauarbeiten | Wand | Außenwand 7-Schalig | WA-LB | 0 | A | 11.25 | 1255HWa0000000069 | NEW | no | yes | 0 | 0 | no | 0 | no | Codetext
 | H2 Ebene +4/ Dachebene | WA-KL | 1407Wa 0000009960 | yes | Codetext | m² | Zimmer- und Holzbauarbeiten | Wand | Außenwand 7-Schalig | WA-KL | 0 | A | 11.25 | 1255HWa0000000069 | NEW | no | yes | 0 | 0 | no | 0 | no | Codetext
 | H2 Ebene +4/ Dachebene | WA-TL | 1407Wa 0000009974 | yes | Codetext | m² | Zimmer- und Holzbauarbeiten | Wand | Außenwand 7-Schalig | WA-TL | 0 | A | 11.25 | 1255HWa0000000069 | NEW | no | yes | 0 | 0 | no | 0 | no | Codetext
 | H2 Ebene +4/ Dachebene | WA-HS | 1407Wa 0000009972 | yes | Codetext | m² | Zimmer- und Holzbauarbeiten | Wand | Außenwand 7-Schalig | WA-HS | 0 | A | 11.25 | 1255HWa0000000069 | NEW | no | yes | 0 | 0 | no | 0 | no | Codetext
 | H2 Ebene +4/ Dachebene | WA-LB | 1407Wa 0000010408 | yes | Codetext | m² | Trockenbauarbeiten | Wand | Außenwand 7-Schalig | WA-LB | 0 | A | 11.25 | 1255HWa0000001424 | NEW |  | yes | 0 | 0 | no | 0 | no | Codetext
 | H2 Ebene +4/ Dachebene | WA-DL | 1407Wa 0000010410 | yes | Codetext | m³ | Zimmer- und Holzbauarbeiten | Wand | Außenwand 7-Schalig | WA-DL | 0 | A | 11.25 | 1255HWa0000001424 | NEW |  | yes | 0 | 0 | no | 0 | no | Codetext | AllplanAttributes - ash D_Detailverweis: DT D; ash D_Plannummer: D1851
 | H2 Ebene +4/ Dachebene | WA-DL | 1407Wa 0000010412 | yes | Codetext | m³ | Zimmer- und Holzbauarbeiten | Wand | Außenwand 7-Schalig | WA-DL | 0 | A | 11.25 | 1255HWa0000001424 | NEW |  | yes | 0 | 0 | no | 0 | no | Codetext
 | H2 Ebene +4/ Dachebene | WA-LB | 1407Wa 0000010414 | yes | Codetext | m² | Trockenbauarbeiten | Wand | Außenwand 7-Schalig | WA-LB | 0 | A | 11.25 | 1255HWa0000001424 | NEW |  | yes | 0 | 0 | no | 0 | no | Codetext
 | H2 Ebene +4/ Dachebene | WA-KL | 1407Wa 0000010416 | yes | Codetext | m² | Zimmer- und Holzbauarbeiten | Wand | Außenwand 7-Schalig | WA-KL | 0 | A | 11.25 | 1255HWa0000001424 | NEW |  | yes | 0 | 0 | no | 0 | no | Codetext
 | H2 Ebene +4/ Dachebene | WA-TL | 1407Wa 0000010418 | yes | Codetext | m² | Zimmer- und Holzbauarbeiten | Wand | Außenwand 7-Schalig | WA-TL | 0 | A | 11.25 | 1255HWa0000001424 | NEW |  | yes | 0 | 0 | no | 0 | no | Codetext
 | H2 Ebene +4/ Dachebene | WA-HS | 1407Wa 0000010420 | yes | Codetext | m² | Zimmer- und Holzbauarbeiten | Wand | Außenwand 7-Schalig | WA-HS | 0 | A | 11.25 | 1255HWa0000001424 | NEW |  | yes | 0 | 0 | no | 0 | no | Codetext
 | H2 Ebene +4/ Dachebene | WA-LB | 1407Wa 0000010422 | yes | Codetext | m² | Trockenbauarbeiten | Wand | Außenwand 7-Schalig | WA-LB | 0 | A | 11.25 | 1255HWa0000001424 | NEW | no | yes | 0 | 0 | no | 0 | no | Codetext
 | H2 Ebene +4/ Dachebene | WA-DL | 1407Wa 0000010424 | yes | Codetext | m³ | Zimmer- und Holzbauarbeiten | Wand | Außenwand 7-Schalig | WA-DL | 0 | A | 11.25 | 1255HWa0000001424 | NEW | no | yes | 0 | 0 | no | 0 | no | Codetext | AllplanAttributes - ash D_Detailverweis: DT D; ash D_Plannummer: D1851
 | H2 Ebene +4/ Dachebene | WA-DL | 1407Wa 0000010426 | yes | Codetext | m³ | Zimmer- und Holzbauarbeiten | Wand | Außenwand 7-Schalig | WA-DL | 0 | A | 11.25 | 1255HWa0000001424 | NEW | no | yes | 0 | 0 | no | 0 | no | Codetext
 | H2 Ebene +4/ Dachebene | WA-LB | 1407Wa 0000010428 | yes | Codetext | m² | Trockenbauarbeiten | Wand | Außenwand 7-Schalig | WA-LB | 0 | A | 11.25 | 1255HWa0000001424 | NEW | no | yes | 0 | 0 | no | 0 | no | Codetext
 | H2 Ebene +4/ Dachebene | WA-KL | 1407Wa 0000010430 | yes | Codetext | m² | Zimmer- und Holzbauarbeiten | Wand | Außenwand 7-Schalig | WA-KL | 0 | A | 11.25 | 1255HWa0000001424 | NEW | no | yes | 0 | 0 | no | 0 | no | Codetext
 | H2 Ebene +4/ Dachebene | WA-TL | 1407Wa 0000010432 | yes | Codetext | m² | Zimmer- und Holzbauarbeiten | Wand | Außenwand 7-Schalig | WA-TL | 0 | A | 11.25 | 1255HWa0000001424 | NEW | no | yes | 0 | 0 | no | 0 | no | Codetext
 | H2 Ebene +4/ Dachebene | WA-HS | 1407Wa 0000010434 | yes | Codetext | m² | Zimmer- und Holzbauarbeiten | Wand | Außenwand 7-Schalig | WA-HS | 0 | A | 11.25 | 1255HWa0000001424 | NEW | no | yes | 0 | 0 | no | 0 | no | Codetext
 | H2 Ebene +4/ Dachebene | WA-LB | 1407Wa 0000010450 | yes | Codetext | m² | Trockenbauarbeiten | Wand | Außenwand 7-Schalig | WA-LB | 0 | A | 11.25 | 1255HWa0000000145 | NEW | no | yes | 0 | 0 | no | 0 | no | Codetext
 | H2 Ebene +4/ Dachebene | WA-DL | 1407Wa 0000010452 | yes | Codetext | m³ | Zimmer- und Holzbauarbeiten | Wand | Außenwand 7-Schalig | WA-DL | 0 | A | 11.25 | 1255HWa0000000145 | NEW | no | yes | 0 | 0 | no | 0 | no | Codetext
 | H2 Ebene +4/ Dachebene | WA-DL | 1407Wa 0000010454 | yes | Codetext | m³ | Zimmer- und Holzbauarbeiten | Wand | Außenwand 7-Schalig | WA-DL | 0 | A | 11.25 | 1255HWa0000000145 | NEW | no | yes | 0 | 0 | no | 0 | no | Codetext
 | H2 Ebene +4/ Dachebene | WA-DL | 1407Wa 0000010456 | yes | Codetext | m³ | Zimmer- und Holzbauarbeiten | Wand | Außenwand 7-Schalig | WA-DL | 0 | A | 11.25 | 1255HWa0000000145 | NEW | no | yes | 0 | 0 | no | 0 | no | Codetext
 | H2 Ebene +4/ Dachebene | WA-LB | 1407Wa 0000010458 | yes | Codetext | m² | Trockenbauarbeiten | Wand | Außenwand 7-Schalig | WA-LB | 0 | A | 11.25 | 1255HWa0000000145 | NEW | no | yes | 0 | 0 | no | 0 | no | Codetext
 | H2 Ebene +4/ Dachebene | WA-KL | 1407Wa 0000010460 | yes | Codetext | m² | Zimmer- und Holzbauarbeiten | Wand | Außenwand 7-Schalig | WA-KL | 0 | A | 11.25 | 1255HWa0000000145 | NEW | no | yes | 0 | 0 | no | 0 | no | Codetext
 | H2 Ebene +4/ Dachebene | WA-TL | 1407Wa 0000010462 | yes | Codetext | m² | Zimmer- und Holzbauarbeiten | Wand | Außenwand 7-Schalig | WA-TL | 0 | A | 11.25 | 1255HWa0000000145 | NEW | no | yes | 0 | 0 | no | 0 | no | Codetext
 | H2 Ebene +4/ Dachebene | WA-HS | 1407Wa 0000010464 | yes | Codetext | m² | Zimmer- und Holzbauarbeiten | Wand | Außenwand 7-Schalig | WA-HS | 0 | A | 11.25 | 1255HWa0000000145 | NEW | no | yes | 0 | 0 | no | 0 | no | Codetext
 | H2 Ebene +4/ Dachebene | WA-LB | 1407Wa 0000010406 | yes | Codetext | m² | Trockenbauarbeiten | Wand | Außenwand 7-Schalig | WA-LB | 0 | A | 11.25 | 1255HWa0000000145 | NEW | no | yes | 0 | 0 | no | 0 | no | Codetext
 | H2 Ebene +4/ Dachebene | WA-DL | 1407Wa 0000010404 | yes | Codetext | m³ | Zimmer- und Holzbauarbeiten | Wand | Außenwand 7-Schalig | WA-DL | 0 | A | 11.25 | 1255HWa0000000145 | NEW | no | yes | 0 | 0 | no | 0 | no | Codetext
 | H2 Ebene +4/ Dachebene | WA-DL | 1407Wa 0000010402 | yes | Codetext | m³ | Zimmer- und Holzbauarbeiten | Wand | Außenwand 7-Schalig | WA-DL | 0 | A | 11.25 | 1255HWa0000000145 | NEW | no | yes | 0 | 0 | no | 0 | no | Codetext
 | H2 Ebene +4/ Dachebene | WA-DL | 1407Wa 0000010400 | yes | Codetext | m³ | Zimmer- und Holzbauarbeiten | Wand | Außenwand 7-Schalig | WA-DL | 0 | A | 11.25 | 1255HWa0000000145 | NEW | no | yes | 0 | 0 | no | 0 | no | Codetext
 | H2 Ebene +4/ Dachebene | WA-LB | 1407Wa 0000010398 | yes | Codetext | m² | Trockenbauarbeiten | Wand | Außenwand 7-Schalig | WA-LB | 0 | A | 11.25 | 1255HWa0000000145 | NEW | no | yes | 0 | 0 | no | 0 | no | Codetext
 | H2 Ebene +4/ Dachebene | WA-KL | 1407Wa 0000010396 | yes | Codetext | m² | Zimmer- und Holzbauarbeiten | Wand | Außenwand 7-Schalig | WA-KL | 0 | A | 11.25 | 1255HWa0000000145 | NEW | no | yes | 0 | 0 | no | 0 | no | Codetext
 | H2 Ebene +4/ Dachebene | WA-TL | 1407Wa 0000010394 | yes | Codetext | m² | Zimmer- und Holzbauarbeiten | Wand | Außenwand 7-Schalig | WA-TL | 0 | A | 11.25 | 1255HWa0000000145 | NEW | no | yes | 0 | 0 | no | 0 | no | Codetext
 | H2 Ebene +4/ Dachebene | WA-HS | 1407Wa 0000010392 | yes | Codetext | m² | Zimmer- und Holzbauarbeiten | Wand | Außenwand 7-Schalig | WA-HS | 0 | A | 11.25 | 1255HWa0000000145 | NEW | no | yes | 0 | 0 | no | 0 | no | Codetext
 | H2 Ebene +4/ Dachebene | WA-LB | 1407Wa 0000010010 | yes | Codetext | m² | Trockenbauarbeiten | Wand | Außenwand 7-Schalig | WA-LB | 0 | A | 11.25 | 1255HWa0811466406 | NEW | no | yes | REI 60-A1 - D,s2-d0 +A1 | 0 | no | 0 | no | Codetext
 | H2 Ebene +4/ Dachebene | WA-HD | 1407Wa 0000010012 | yes | Codetext | m³ | Zimmer- und Holzbauarbeiten | Wand | Außenwand 7-Schalig | WA-HD | 0 | A | 11.25 | 1255HWa0811466406 | NEW | yes | yes | REI 60-A1 - D,s2-d0 +A1 | 0 | no | 0 | no | Codetext
 | H2 Ebene +4/ Dachebene | WA-DL | 1407Wa 0000010014 | yes | Codetext | m³ | Zimmer- und Holzbauarbeiten | Wand | Außenwand 7-Schalig | WA-DL | 0 | A | 11.25 | 1255HWa0811466406 | NEW | no | yes | REI 60-A1 - D,s2-d0 +A1 | 0 | no | 0 | no | Codetext
 | H2 Ebene +4/ Dachebene | WA-LB | 1407Wa 0000010016 | yes | Codetext | m² | Trockenbauarbeiten | Wand | Außenwand 7-Schalig | WA-LB | 0 | A | 11.25 | 1255HWa0811456429 | NEW | no | yes | 0 | 0 | no | 0 | no | Codetext
 | H2 Ebene +4/ Dachebene | WA-KL | 1407Wa 0000010018 | yes | Codetext | m² | Zimmer- und Holzbauarbeiten | Wand | Außenwand 7-Schalig | WA-KL | 0 | A | 11.25 | 1255HWa0811466406 | NEW | no | yes | REI 60-A1 - D,s2-d0 +A1 | 0 | no | 0 | no | Codetext
 | H2 Ebene +4/ Dachebene | WA-TL | 1407Wa 0000010020 | yes | Codetext | m² | Zimmer- und Holzbauarbeiten | Wand | Außenwand 7-Schalig | WA-TL | 0 | A | 11.25 | 1255HWa0811466406 | NEW | no | yes | REI 60-A1 - D,s2-d0 +A1 | 0 | no | 0 | no | Codetext
 | H2 Ebene +4/ Dachebene | WA-HS | 1407Wa 0000010022 | yes | Codetext | m² | Zimmer- und Holzbauarbeiten | Wand | Außenwand 7-Schalig | WA-HS | 0 | A | 11.25 | 1255HWa0811466406 | NEW | no | yes | REI 60-A1 - D,s2-d0 +A1 | 0 | no | 0 | no | Codetext
 | H2 Ebene +4/ Dachebene | WA-LB | 1407Wa 0000010172 | yes | Codetext | m² | Trockenbauarbeiten | Wand | Außenwand 7-Schalig | WA-LB | 0 | A | 11.25 | 1255HWa0811466406 | NEW |  | yes | REI 60-A1 - D,s2-d0 +A1 | 0 | no | 0 | no | Codetext
 | H2 Ebene +4/ Dachebene | WA-HD | 1407Wa 0000010174 | yes | Codetext | m³ | Zimmer- und Holzbauarbeiten | Wand | Außenwand 7-Schalig | WA-HD | 0 | A | 11.25 | 1255HWa0811466406 | NEW |  | yes | REI 60-A1 - D,s2-d0 +A1 | 0 | no | 0 | no | Codetext
 | H2 Ebene +4/ Dachebene | WA-DL | 1407Wa 0000010176 | yes | Codetext | m³ | Zimmer- und Holzbauarbeiten | Wand | Außenwand 7-Schalig | WA-DL | 0 | A | 11.25 | 1255HWa0811466406 | NEW |  | yes | REI 60-A1 - D,s2-d0 +A1 | 0 | no | 0 | no | Codetext
 | H2 Ebene +4/ Dachebene | WA-LB | 1407Wa 0000010178 | yes | Codetext | m² | Trockenbauarbeiten | Wand | Außenwand 7-Schalig | WA-LB | 0 | A | 11.25 | 1255HWa0811456429 | NEW |  | yes | 0 | 0 | no | 0 | no | Codetext
 | H2 Ebene +4/ Dachebene | WA-KL | 1407Wa 0000010180 | yes | Codetext | m² | Zimmer- und Holzbauarbeiten | Wand | Außenwand 7-Schalig | WA-KL | 0 | A | 11.25 | 1255HWa0811466406 | NEW |  | yes | REI 60-A1 - D,s2-d0 +A1 | 0 | no | 0 | no | Codetext
 | H2 Ebene +4/ Dachebene | WA-TL | 1407Wa 0000010182 | yes | Codetext | m² | Zimmer- und Holzbauarbeiten | Wand | Außenwand 7-Schalig | WA-TL | 0 | A | 11.25 | 1255HWa0811466406 | NEW |  | yes | REI 60-A1 - D,s2-d0 +A1 | 0 | no | 0 | no | Codetext
 | H2 Ebene +4/ Dachebene | WA-HS | 1407Wa 0000010184 | yes | Codetext | m² | Zimmer- und Holzbauarbeiten | Wand | Außenwand 7-Schalig | WA-HS | 0 | A | 11.25 | 1255HWa0811466406 | NEW |  | yes | REI 60-A1 - D,s2-d0 +A1 | 0 | no | 0 | no | Codetext
 | H2 Ebene +3 | ZBL | 1255Wa 0811498709 | yes |  | m | Dachabdichtungsarbeiten | Attikablech |  | ZBL |  |  |  |  | NEW | no | yes | AllplanAttributes - ash D_Detailverweis: Sys-Gel.; ash D_Plannummer: D9579; Attributset-Objekt: Covering
 | H2 Ebene +3 | ZBL | 1255Wa 0811498828 | yes |  | m | Dachabdichtungsarbeiten | Attikablech |  | ZBL |  |  |  |  | NEW | no | yes | AllplanAttributes - ash D_Detailverweis: Sys-Gel.; ash D_Plannummer: D9579; Attributset-Objekt: Covering
2x Gipsfaserplatte | H2 Ebene +3 | WA-LB | 1255Wa 0811456294 | yes |  | m² | Trockenbauarbeiten | Wand | 2x Gipsfaserplatte | WA-LB |  |  | 11.25 | 1255HWa0811456284 | NEW | no | yes | REI 60-A1 - D,s2-d0 +A1
2x Gipsfaserplatte | H2 Ebene +3 | WA-LB | 1255Wa 0811456293 | yes |  | m² | Trockenbauarbeiten | Wand | 2x Gipsfaserplatte | WA-LB |  |  | 11.25 | 1255HWa0811456284 | NEW | no | yes | 0 | 0.9 |  | 32 | AllplanAttributes - Sicherheitsklasse: -; Sonnenschutztyp: Movable; g-Wert: 0,51
Holzständer + Zwischendämmung | H2 Ebene +3 | WA-HD | 1255Wa 0811456292 | yes |  | m³ | Zimmer- und Holzbauarbeiten | Wand | Holzständer + Zwischendämmung | WA-HD |  |  | 11.25 | 1255HWa0811456284 | NEW | no | yes | REI 60-A1 - D,s2-d0 +A1 | AllplanAttributes - ash D_Detailverweis: DT A; ash D_Plannummer: D1850
 | H2 Ebene +3 | WA-LB | 1255Wa 0811456291 | yes | Codetext | m² | Trockenbauarbeiten | Wand | Außenwand 7-Schalig | WA-LB | 0 | A | 11.25 | 1255HWa0811456284 | NEW | no | yes | 0 | 0.9 | no | 32 | no | Codetext | AllplanAttributes - Sicherheitsklasse: -; Sonnenschutztyp: Movable; g-Wert: 0,51
 | H2 Ebene +3 | WA-LB | 1255Wa 0811456290 | yes | Codetext | m² | Trockenbauarbeiten | Wand | Außenwand 7-Schalig | WA-LB | 0 | A | 11.25 | 1255HWa0811456284 | NEW | no | yes | 0 | 0 | no | 0 | no | Codetext
Staffel + Zwischendämmung | H2 Ebene +3 | WA-DL | 1255Wa 0811456289 | yes |  | m³ | Zimmer- und Holzbauarbeiten | Wand | Staffel + Zwischendämmung | WA-DL |  |  | 11.25 | 1255HWa0811456284 | NEW | no | yes | REI 60-A1 - D,s2-d0 +A1
Konterlattung | H2 Ebene +3 | WA-KL | 1255Wa 0811456288 | yes |  | m² | Zimmer- und Holzbauarbeiten | Wand | Konterlattung | WA-KL |  |  | 11.25 | 1255HWa0811456284 | NEW | no | yes | REI 60-A1 - D,s2-d0 +A1
Traglattung | H2 Ebene +3 | WA-TL | 1255Wa 0811456287 | yes |  | m² | Zimmer- und Holzbauarbeiten | Wand | Traglattung | WA-TL |  |  | 11.25 | 1255HWa0811456284 | NEW | no | yes | REI 60-A1 - D,s2-d0 +A1
Holzschindel | H2 Ebene +3 | WA-HS | 1255Wa 0811456286 | yes |  | m² | Zimmer- und Holzbauarbeiten | Wand | Holzschindel | WA-HS |  |  | 11.25 | 1255HWa0811456284 | NEW | no | yes | REI 60-A1 - D,s2-d0 +A1 | AllplanAttributes - ash D_Detailverweis: DT 4; ash D_Plannummer: D1615
 | H2 Ebene +3 | WA-LB | 1255Wa 0811455534 | yes | Codetext | m² | Trockenbauarbeiten | Wand | Außenwand 7-Schalig | WA-LB | 0 | A | 11.25 | 1255HWa0811455526 | NEW | no | yes | 0 | 0 | no | 0 | no | Codetext
 | H2 Ebene +3 | WA-DL | 1255Wa 0811455533 | yes | Codetext | m³ | Zimmer- und Holzbauarbeiten | Wand | Außenwand 7-Schalig | WA-DL | 0 | A | 11.25 | 1255HWa0811455526 | NEW | no | yes | 0 | 0 | no | 0 | no | Codetext
 | H2 Ebene +3 | WA-DL | 1255Wa 0811455532 | yes | Codetext | m³ | Zimmer- und Holzbauarbeiten | Wand | Außenwand 7-Schalig | WA-DL | 0 | A | 11.25 | 1255HWa0811455526 | NEW | no | yes | 0 | 0 | no | 0 | no | Codetext
 | H2 Ebene +3 | WA-LB | 1255Wa 0811455531 | yes | Codetext | m² | Trockenbauarbeiten | Wand | Außenwand 7-Schalig | WA-LB | 0 | A | 11.25 | 1255HWa0811455526 | NEW | no | yes | 0 | 0 | no | 0 | no | Codetext
 | H2 Ebene +3 | WA-KL | 1255Wa 0811455530 | yes | Codetext | m² | Zimmer- und Holzbauarbeiten | Wand | Außenwand 7-Schalig | WA-KL | 0 | A | 11.25 | 1255HWa0811455526 | NEW | no | yes | 0 | 0 | no | 0 | no | Codetext
 | H2 Ebene +3 | WA-TL | 1255Wa 0811455529 | yes | Codetext | m² | Zimmer- und Holzbauarbeiten | Wand | Außenwand 7-Schalig | WA-TL | 0 | A | 11.25 | 1255HWa0811455526 | NEW | no | yes | 0 | 0 | no | 0 | no | Codetext
 | H2 Ebene +3 | WA-HS | 1255Wa 0811455528 | yes | Codetext | m² | Zimmer- und Holzbauarbeiten | Wand | Außenwand 7-Schalig | WA-HS | 0 | A | 11.25 | 1255HWa0811455526 | NEW | no | yes | 0 | 0 | no | 0 | no | Codetext
2x Gipsfaserplatte | H2 Ebene +3 | WA-LB | 1255Wa 0000013343 | yes |  | m² | Trockenbauarbeiten | Wand | 2x Gipsfaserplatte | WA-LB |  |  | 11.25 | 1255HWa0000013335 | NEW | no | yes | REI 60-A1 - D,s2-d0 +A1
Holzständer + Zwischendämmung | H2 Ebene +3 | WA-HD | 1255Wa 0000013342 | yes |  | m³ | Zimmer- und Holzbauarbeiten | Wand | Holzständer + Zwischendämmung | WA-HD |  |  | 11.25 | 1255HWa0000013335 | NEW | no | yes | REI 60-A1 - D,s2-d0 +A1
Staffel + Zwischendämmung | H2 Ebene +3 | WA-DL | 1255Wa 0000013341 | yes |  | m³ | Zimmer- und Holzbauarbeiten | Wand | Staffel + Zwischendämmung | WA-DL |  |  | 11.25 | 1255HWa0000013335 | NEW | no | yes | REI 60-A1 - D,s2-d0 +A1
 | H2 Ebene +3 | WA-LB | 1255Wa 0000013340 | yes | Codetext | m² | Trockenbauarbeiten | Wand | Außenwand 7-Schalig | WA-LB | 0 | A | 11.25 | 1255HWa0000013335 | NEW | no | yes | 0 | 0 | no | 0 | no | Codetext
Konterlattung | H2 Ebene +3 | WA-KL | 1255Wa 0000013339 | yes |  | m² | Zimmer- und Holzbauarbeiten | Wand | Konterlattung | WA-KL |  |  | 11.25 | 1255HWa0000013335 | NEW | no | yes | REI 60-A1 - D,s2-d0 +A1
Traglattung | H2 Ebene +3 | WA-TL | 1255Wa 0000013338 | yes |  | m² | Zimmer- und Holzbauarbeiten | Wand | Traglattung | WA-TL |  |  | 11.25 | 1255HWa0000013335 | NEW | no | yes | REI 60-A1 - D,s2-d0 +A1
Holzschindel | H2 Ebene +3 | WA-HS | 1255Wa 0000013337 | yes |  | m² | Zimmer- und Holzbauarbeiten | Wand | Holzschindel | WA-HS |  |  | 11.25 | 1255HWa0000013335 | NEW | no | yes | REI 60-A1 - D,s2-d0 +A1
 | H2 Ebene +3 | WA-LB | 1255Wa 0000013257 | yes | Codetext | m² | Trockenbauarbeiten | Wand | Außenwand 7-Schalig | WA-LB | 0 | A | 11.25 | 1255HWa0000013249 | NEW | no | yes | 0 | 0 | no | 0 | no | Codetext
 | H2 Ebene +3 | WA-DL | 1255Wa 0000013256 | yes | Codetext | m³ | Zimmer- und Holzbauarbeiten | Wand | Außenwand 7-Schalig | WA-DL | 0 | A | 11.25 | 1255HWa0000013249 | NEW | no | yes | 0 | 0 | no | 0 | no | Codetext
 | H2 Ebene +3 | WA-DL | 1255Wa 0000013255 | yes | Codetext | m³ | Zimmer- und Holzbauarbeiten | Wand | Außenwand 7-Schalig | WA-DL | 0 | A | 11.25 | 1255HWa0000013249 | NEW | no | yes | 0 | 0 | no | 0 | no | Codetext
 | H2 Ebene +3 | WA-LB | 1255Wa 0000013254 | yes | Codetext | m² | Trockenbauarbeiten | Wand | Außenwand 7-Schalig | WA-LB | 0 | A | 11.25 | 1255HWa0000013249 | NEW | no | yes | 0 | 0 | no | 0 | no | Codetext
 | H2 Ebene +3 | WA-KL | 1255Wa 0000013253 | yes | Codetext | m² | Zimmer- und Holzbauarbeiten | Wand | Außenwand 7-Schalig | WA-KL | 0 | A | 11.25 | 1255HWa0000013249 | NEW | no | yes | 0 | 0 | no | 0 | no | Codetext
 | H2 Ebene +3 | WA-TL | 1255Wa 0000013252 | yes | Codetext | m² | Zimmer- und Holzbauarbeiten | Wand | Außenwand 7-Schalig | WA-TL | 0 | A | 11.25 | 1255HWa0000013249 | NEW | no | yes | 0 | 0 | no | 0 | no | Codetext
 | H2 Ebene +3 | WA-HS | 1255Wa 0000013251 | yes | Codetext | m² | Zimmer- und Holzbauarbeiten | Wand | Außenwand 7-Schalig | WA-HS | 0 | A | 11.25 | 1255HWa0000013249 | NEW | no | yes | 0 | 0 | no | 0 | no | Codetext
2x Gipsfaserplatte | H2 Ebene +3 | WA-LB | 1255Wa 0000013171 | yes |  | m² | Trockenbauarbeiten | Wand | 2x Gipsfaserplatte | WA-LB |  |  | 11.25 | 1255HWa0000013163 | NEW | no | yes | REI 60-A1 - D,s2-d0 +A1
Holzständer + Zwischendämmung | H2 Ebene +3 | WA-HD | 1255Wa 0000013170 | yes |  | m³ | Zimmer- und Holzbauarbeiten | Wand | Holzständer + Zwischendämmung | WA-HD |  |  | 11.25 | 1255HWa0000013163 | NEW | no | yes | REI 60-A1 - D,s2-d0 +A1
Staffel + Zwischendämmung | H2 Ebene +3 | WA-DL | 1255Wa 0000013169 | yes |  | m³ | Zimmer- und Holzbauarbeiten | Wand | Staffel + Zwischendämmung | WA-DL |  |  | 11.25 | 1255HWa0000013163 | NEW | no | yes | REI 60-A1 - D,s2-d0 +A1
 | H2 Ebene +3 | WA-LB | 1255Wa 0000013168 | yes | Codetext | m² | Trockenbauarbeiten | Wand | Außenwand 7-Schalig | WA-LB | 0 | A | 11.25 | 1255HWa0000013163 | NEW | no | yes | 0 | 0 | no | 0 | no | Codetext
Konterlattung | H2 Ebene +3 | WA-KL | 1255Wa 0000013167 | yes |  | m² | Zimmer- und Holzbauarbeiten | Wand | Konterlattung | WA-KL |  |  | 11.25 | 1255HWa0000013163 | NEW | no | yes | REI 60-A1 - D,s2-d0 +A1
Traglattung | H2 Ebene +3 | WA-TL | 1255Wa 0000013166 | yes |  | m² | Zimmer- und Holzbauarbeiten | Wand | Traglattung | WA-TL |  |  | 11.25 | 1255HWa0000013163 | NEW | no | yes | REI 60-A1 - D,s2-d0 +A1
Holzschindel | H2 Ebene +3 | WA-HS | 1255Wa 0000013165 | yes |  | m² | Zimmer- und Holzbauarbeiten | Wand | Holzschindel | WA-HS |  |  | 11.25 | 1255HWa0000013163 | NEW | no | yes | REI 60-A1 - D,s2-d0 +A1
 | H2 Ebene +3 | WA-LB | 1255Wa 0000013072 | yes | Codetext | m² | Trockenbauarbeiten | Wand | Außenwand 7-Schalig | WA-LB | 0 | A | 11.25 | 1255HWa0000013053 | NEW | no | yes | 0 | 0 | no | 0 | no | Codetext
 | H2 Ebene +3 | WA-DL | 1255Wa 0000013071 | yes | Codetext | m³ | Zimmer- und Holzbauarbeiten | Wand | Außenwand 7-Schalig | WA-DL | 0 | A | 11.25 | 1255HWa0000013053 | NEW | no | yes | 0 | 0 | no | 0 | no | Codetext
 | H2 Ebene +3 | WA-DL | 1255Wa 0000013066 | yes | Codetext | m³ | Zimmer- und Holzbauarbeiten | Wand | Außenwand 7-Schalig | WA-DL | 0 | A | 11.25 | 1255HWa0000013053 | NEW | no | yes | 0 | 0 | no | 0 | no | Codetext
 | H2 Ebene +3 | WA-LB | 1255Wa 0000013069 | yes | Codetext | m² | Trockenbauarbeiten | Wand | Außenwand 7-Schalig | WA-LB | 0 | A | 11.25 | 1255HWa0000013053 | NEW | no | yes | 0 | 0 | no | 0 | no | Codetext
 | H2 Ebene +3 | WA-KL | 1255Wa 0000013070 | yes | Codetext | m² | Zimmer- und Holzbauarbeiten | Wand | Außenwand 7-Schalig | WA-KL | 0 | A | 11.25 | 1255HWa0000013053 | NEW | no | yes | 0 | 0 | no | 0 | no | Codetext
 | H2 Ebene +3 | WA-TL | 1255Wa 0000013067 | yes | Codetext | m² | Zimmer- und Holzbauarbeiten | Wand | Außenwand 7-Schalig | WA-TL | 0 | A | 11.25 | 1255HWa0000013053 | NEW | no | yes | 0 | 0 | no | 0 | no | Codetext
 | H2 Ebene +3 | WA-HS | 1255Wa 0000013068 | yes | Codetext | m² | Zimmer- und Holzbauarbeiten | Wand | Außenwand 7-Schalig | WA-HS | 0 | A | 11.25 | 1255HWa0000013053 | NEW | no | yes | 0 | 0 | no | 0 | no | Codetext
 | H2 Ebene +3 | WA-STB | 1255Wa 0000013028 | yes | Codetext | m² | Zimmer- und Holzbauarbeiten | Wand | Außenwand 2-Schalig | WA-STB | 0 | A | 11.25 | 1255HWa0000013027 | NEW |  | yes | 0 | 0 | no | 0 | no | Codetext
 | H2 Ebene +3 | WA-DL | 1255Wa 0000013029 | yes | Codetext | m³ | Zimmer- und Holzbauarbeiten | Wand | Außenwand 2-Schalig | WA-DL | 0 | A | 11.25 | 1255HWa0000013027 | NEW |  | yes | 0 | 0 | no | 0 | no | Codetext
 | H2 Ebene +3 | WA-LB | 1255Wa 0000013030 | yes | Codetext | m² | Trockenbauarbeiten | Wand | Außenwand 2-Schalig | WA-LB | 0 | A | 11.25 | 1255HWa0000013027 | NEW |  | yes | 0 | 0 | no | 0 | no | Codetext
 | H2 Ebene +3 | WA-KL | 1255Wa 0000013031 | yes | Codetext | m² | Zimmer- und Holzbauarbeiten | Wand | Außenwand 2-Schalig | WA-KL | 0 | A | 11.25 | 1255HWa0000013027 | NEW |  | yes | 0 | 0 | no | 0 | no | Codetext
 | H2 Ebene +3 | WA-TL | 1255Wa 0000013032 | yes | Codetext | m² | Zimmer- und Holzbauarbeiten | Wand | Außenwand 2-Schalig | WA-TL | 0 | A | 11.25 | 1255HWa0000013027 | NEW |  | yes | 0 | 0 | no | 0 | no | Codetext
 | H2 Ebene +3 | WA-HS | 1255Wa 0811401092 | yes | Codetext | m² | Zimmer- und Holzbauarbeiten | Wand | Außenwand 2-Schalig | WA-HS | 0 | A | 11.25 | 1255HWa0000013027 | NEW |  | yes | 0 | 0 | no | 0 | no | Codetext
 | H2 Ebene +3 | WA-STB | 1255Wa 0811522201 | yes | Codetext | m² | Zimmer- und Holzbauarbeiten | Wand | Außenwand 2-Schalig | WA-STB | 0 | A | 11.25 | 1255HWa0000013027 | NEW |  | yes | 0 | 0 | no | 0 | no | Codetext
 | H2 Ebene +3 | WA-DL | 1255Wa 0811522202 | yes | Codetext | m³ | Zimmer- und Holzbauarbeiten | Wand | Außenwand 2-Schalig | WA-DL | 0 | A | 11.25 | 1255HWa0000013027 | NEW |  | yes | 0 | 0 | no | 0 | no | Codetext
 | H2 Ebene +3 | WA-LB | 1255Wa 0811522203 | yes | Codetext | m² | Trockenbauarbeiten | Wand | Außenwand 2-Schalig | WA-LB | 0 | A | 11.25 | 1255HWa0000013027 | NEW |  | yes | 0 | 0 | no | 0 | no | Codetext
 | H2 Ebene +3 | WA-KL | 1255Wa 0811522204 | yes | Codetext | m² | Zimmer- und Holzbauarbeiten | Wand | Außenwand 2-Schalig | WA-KL | 0 | A | 11.25 | 1255HWa0000013027 | NEW |  | yes | 0 | 0 | no | 0 | no | Codetext
 | H2 Ebene +3 | WA-TL | 1255Wa 0811522205 | yes | Codetext | m² | Zimmer- und Holzbauarbeiten | Wand | Außenwand 2-Schalig | WA-TL | 0 | A | 11.25 | 1255HWa0000013027 | NEW |  | yes | 0 | 0 | no | 0 | no | Codetext
 | H2 Ebene +3 | WA-HS | 1255Wa 0811522206 | yes | Codetext | m² | Zimmer- und Holzbauarbeiten | Wand | Außenwand 2-Schalig | WA-HS | 0 | A | 11.25 | 1255HWa0000013027 | NEW |  | yes | 0 | 0 | no | 0 | no | Codetext
 | H2 Ebene +3 | WA-STB | 1255Wa 0000001000 | yes | Codetext | m² | Zimmer- und Holzbauarbeiten | Wand | Außenwand 2-Schalig | WA-STB | 0 | A | 11.25 | 1255HWa0000000242 | NEW |  | yes | 0 | 0 | no | 0 | no | Codetext | AllplanAttributes - ash D_Detailverweis: DT 3; ash D_Plannummer: D1615
 | H2 Ebene +3 | WA-DL | 1255Wa 0000000993 | yes | Codetext | m³ | Zimmer- und Holzbauarbeiten | Wand | Außenwand 2-Schalig | WA-DL | 0 | A | 11.25 | 1255HWa0000000242 | NEW |  | yes | 0 | 0 | no | 0 | no | Codetext
 | H2 Ebene +3 | WA-LB | 1255Wa 0000000986 | yes | Codetext | m² | Trockenbauarbeiten | Wand | Außenwand 2-Schalig | WA-LB | 0 | A | 11.25 | 1255HWa0000000242 | NEW |  | yes | 0 | 0 | no | 0 | no | Codetext
 | H2 Ebene +3 | WA-KL | 1255Wa 0000000979 | yes | Codetext | m² | Zimmer- und Holzbauarbeiten | Wand | Außenwand 2-Schalig | WA-KL | 0 | A | 11.25 | 1255HWa0000000242 | NEW |  | yes | 0 | 0 | no | 0 | no | Codetext
 | H2 Ebene +3 | WA-TL | 1255Wa 0000000972 | yes | Codetext | m² | Zimmer- und Holzbauarbeiten | Wand | Außenwand 2-Schalig | WA-TL | 0 | A | 11.25 | 1255HWa0000000242 | NEW |  | yes | 0 | 0 | no | 0 | no | Codetext
 | H2 Ebene +3 | WA-HS | 1255Wa 0811400273 | yes | Codetext | m² | Zimmer- und Holzbauarbeiten | Wand | Außenwand 2-Schalig | WA-HS | 0 | A | 11.25 | 1255HWa0000000242 | NEW |  | yes | 0 | 0 | no | 0 | no | Codetext
 | H2 Ebene +3 | WA-STB | 1255Wa 0000013003 | yes | Codetext | m² | Zimmer- und Holzbauarbeiten | Wand | Außenwand 2-Schalig | WA-STB | 0 | A | 11.25 | 1255HWa0000013002 | NEW |  | yes | 0 | 0 | no | 0 | no | Codetext
 | H2 Ebene +3 | WA-DL | 1255Wa 0000013004 | yes | Codetext | m³ | Zimmer- und Holzbauarbeiten | Wand | Außenwand 2-Schalig | WA-DL | 0 | A | 11.25 | 1255HWa0000013002 | NEW |  | yes | 0 | 0 | no | 0 | no | Codetext
 | H2 Ebene +3 | WA-LB | 1255Wa 0000013005 | yes | Codetext | m² | Trockenbauarbeiten | Wand | Außenwand 2-Schalig | WA-LB | 0 | A | 11.25 | 1255HWa0000013002 | NEW |  | yes | 0 | 0 | no | 0 | no | Codetext
 | H2 Ebene +3 | WA-KL | 1255Wa 0000013006 | yes | Codetext | m² | Zimmer- und Holzbauarbeiten | Wand | Außenwand 2-Schalig | WA-KL | 0 | A | 11.25 | 1255HWa0000013002 | NEW |  | yes | 0 | 0 | no | 0 | no | Codetext
 | H2 Ebene +3 | WA-TL | 1255Wa 0000013007 | yes | Codetext | m² | Zimmer- und Holzbauarbeiten | Wand | Außenwand 2-Schalig | WA-TL | 0 | A | 11.25 | 1255HWa0000013002 | NEW |  | yes | 0 | 0 | no | 0 | no | Codetext
 | H2 Ebene +3 | WA-HS | 1255Wa 0811401059 | yes | Codetext | m² | Zimmer- und Holzbauarbeiten | Wand | Außenwand 2-Schalig | WA-HS | 0 | A | 11.25 | 1255HWa0000013002 | NEW |  | yes | 0 | 0 | no | 0 | no | Codetext
 | H2 Ebene +3 | WA-STB | 1255Wa 0811426981 | yes | Codetext | m² | Zimmer- und Holzbauarbeiten | Wand | Außenwand 2-Schalig | WA-STB | 0 | A | 11.25 | 1255HWa0811426980 | NEW |  | yes | 0 | 0 | no | 0 | no | Codetext
 | H2 Ebene +3 | WA-DL | 1255Wa 0811426982 | yes | Codetext | m³ | Zimmer- und Holzbauarbeiten | Wand | Außenwand 2-Schalig | WA-DL | 0 | A | 11.25 | 1255HWa0811426980 | NEW |  | yes | 0 | 0 | no | 0 | no | Codetext
 | H2 Ebene +3 | WA-LB | 1255Wa 0811426983 | yes | Codetext | m² | Trockenbauarbeiten | Wand | Außenwand 2-Schalig | WA-LB | 0 | A | 11.25 | 1255HWa0811426980 | NEW |  | yes | 0 | 0 | no | 0 | no | Codetext
 | H2 Ebene +3 | WA-KL | 1255Wa 0811426984 | yes | Codetext | m² | Zimmer- und Holzbauarbeiten | Wand | Außenwand 2-Schalig | WA-KL | 0 | A | 11.25 | 1255HWa0811426980 | NEW |  | yes | 0 | 0 | no | 0 | no | Codetext
 | H2 Ebene +3 | WA-TL | 1255Wa 0811426985 | yes | Codetext | m² | Zimmer- und Holzbauarbeiten | Wand | Außenwand 2-Schalig | WA-TL | 0 | A | 11.25 | 1255HWa0811426980 | NEW |  | yes | 0 | 0 | no | 0 | no | Codetext
 | H2 Ebene +3 | WA-HS | 1255Wa 0811426986 | yes | Codetext | m² | Zimmer- und Holzbauarbeiten | Wand | Außenwand 2-Schalig | WA-HS | 0 | A | 11.25 | 1255HWa0811426980 | NEW |  | yes | 0 | 0 | no | 0 | no | Codetext
 | H2 Ebene +3 | WA-LB | 1255Wa 0000000935 | yes | Codetext | m² | Trockenbauarbeiten | Wand | Außenwand 7-Schalig | WA-LB | 0 | A | 11.25 | 1255HWa0000000075 | NEW | no | yes | 0 | 0 | no | 0 | no | Codetext
 | H2 Ebene +3 | WA-DL | 1255Wa 0000000937 | yes | Codetext | m³ | Zimmer- und Holzbauarbeiten | Wand | Außenwand 7-Schalig | WA-DL | 0 | A | 11.25 | 1255HWa0000000075 | NEW | no | yes | 0 | 0 | no | 0 | no | Codetext
 | H2 Ebene +3 | WA-DL | 1255Wa 0000000939 | yes | Codetext | m³ | Zimmer- und Holzbauarbeiten | Wand | Außenwand 7-Schalig | WA-DL | 0 | A | 11.25 | 1255HWa0000000075 | NEW | no | yes | 0 | 0 | no | 0 | no | Codetext
 | H2 Ebene +3 | WA-LB | 1255Wa 0000000941 | yes | Codetext | m² | Trockenbauarbeiten | Wand | Außenwand 7-Schalig | WA-LB | 0 | A | 11.25 | 1255HWa0000000075 | NEW | no | yes | 0 | 0 | no | 0 | no | Codetext
 | H2 Ebene +3 | WA-KL | 1255Wa 0000000943 | yes | Codetext | m² | Zimmer- und Holzbauarbeiten | Wand | Außenwand 7-Schalig | WA-KL | 0 | A | 11.25 | 1255HWa0000000075 | NEW | no | yes | 0 | 0 | no | 0 | no | Codetext
 | H2 Ebene +3 | WA-TL | 1255Wa 0000000945 | yes | Codetext | m² | Zimmer- und Holzbauarbeiten | Wand | Außenwand 7-Schalig | WA-TL | 0 | A | 11.25 | 1255HWa0000000075 | NEW | no | yes | 0 | 0 | no | 0 | no | Codetext
 | H2 Ebene +3 | WA-HS | 1255Wa 0000000947 | yes | Codetext | m² | Zimmer- und Holzbauarbeiten | Wand | Außenwand 7-Schalig | WA-HS | 0 | A | 11.25 | 1255HWa0000000075 | NEW | no | yes | 0 | 0 | no | 0 | no | Codetext
2x Gipsfaserplatte | H2 Ebene +3 | WA-LB | 1255Wa 0000012558 | yes |  | m² | Trockenbauarbeiten | Wand | 2x Gipsfaserplatte | WA-LB |  |  | 11.25 | 1255HWa0000012550 | NEW | no | yes | REI 60-A1 - D,s2-d0 +A1
Holzständer + Zwischendämmung | H2 Ebene +3 | WA-HD | 1255Wa 0000012557 | yes |  | m³ | Zimmer- und Holzbauarbeiten | Wand | Holzständer + Zwischendämmung | WA-HD |  |  | 11.25 | 1255HWa0000012550 | NEW | no | yes | REI 60-A1 - D,s2-d0 +A1
Staffel + Zwischendämmung | H2 Ebene +3 | WA-DL | 1255Wa 0000012556 | yes |  | m³ | Zimmer- und Holzbauarbeiten | Wand | Staffel + Zwischendämmung | WA-DL |  |  | 11.25 | 1255HWa0000012550 | NEW | no | yes | REI 60-A1 - D,s2-d0 +A1
 | H2 Ebene +3 | WA-LB | 1255Wa 0000012555 | yes | Codetext | m² | Trockenbauarbeiten | Wand | Außenwand 7-Schalig | WA-LB | 0 | A | 11.25 | 1255HWa0000012550 | NEW | no | yes | 0 | 0 | no | 0 | no | Codetext
Konterlattung | H2 Ebene +3 | WA-KL | 1255Wa 0000012554 | yes |  | m² | Zimmer- und Holzbauarbeiten | Wand | Konterlattung | WA-KL |  |  | 11.25 | 1255HWa0000012550 | NEW | no | yes | REI 60-A1 - D,s2-d0 +A1
Traglattung | H2 Ebene +3 | WA-TL | 1255Wa 0000012553 | yes |  | m² | Zimmer- und Holzbauarbeiten | Wand | Traglattung | WA-TL |  |  | 11.25 | 1255HWa0000012550 | NEW | no | yes | REI 60-A1 - D,s2-d0 +A1
Holzschindel | H2 Ebene +3 | WA-HS | 1255Wa 0000012552 | yes |  | m² | Zimmer- und Holzbauarbeiten | Wand | Holzschindel | WA-HS |  |  | 11.25 | 1255HWa0000012550 | NEW | no | yes | REI 60-A1 - D,s2-d0 +A1
 | H2 Ebene +3 | WA-LB | 1255Wa 0811523298 | yes | Codetext | m² | Trockenbauarbeiten | Wand | Außenwand 7-Schalig | WA-LB | 0 | A | 11.25 | 1255HWa0000012425 | NEW | no | yes | 0 | 0 | no | 0 | no | Codetext
 | H2 Ebene +3 | WA-DL | 1255Wa 0811523303 | yes | Codetext | m³ | Zimmer- und Holzbauarbeiten | Wand | Außenwand 7-Schalig | WA-DL | 0 | A | 11.25 | 1255HWa0000012425 | NEW | no | yes | 0 | 0 | no | 0 | no | Codetext | AllplanAttributes - ash D_Detailverweis: DT C; ash D_Plannummer: D1851
 | H2 Ebene +3 | WA-DL | 1255Wa 0811523302 | yes | Codetext | m³ | Zimmer- und Holzbauarbeiten | Wand | Außenwand 7-Schalig | WA-DL | 0 | A | 11.25 | 1255HWa0000012425 | NEW | no | yes | 0 | 0 | no | 0 | no | Codetext
 | H2 Ebene +3 | WA-LB | 1255Wa 0811523301 | yes | Codetext | m² | Trockenbauarbeiten | Wand | Außenwand 7-Schalig | WA-LB | 0 | A | 11.25 | 1255HWa0000012425 | NEW | no | yes | 0 | 0 | no | 0 | no | Codetext
 | H2 Ebene +3 | WA-KL | 1255Wa 0811523300 | yes | Codetext | m² | Zimmer- und Holzbauarbeiten | Wand | Außenwand 7-Schalig | WA-KL | 0 | A | 11.25 | 1255HWa0000012425 | NEW | no | yes | 0 | 0 | no | 0 | no | Codetext
 | H2 Ebene +3 | WA-TL | 1255Wa 0811523299 | yes | Codetext | m² | Zimmer- und Holzbauarbeiten | Wand | Außenwand 7-Schalig | WA-TL | 0 | A | 11.25 | 1255HWa0000012425 | NEW | no | yes | 0 | 0 | no | 0 | no | Codetext
 | H2 Ebene +3 | WA-HS | 1255Wa 0811523297 | yes | Codetext | m² | Zimmer- und Holzbauarbeiten | Wand | Außenwand 7-Schalig | WA-HS | 0 | A | 11.25 | 1255HWa0000012425 | NEW | no | yes | 0 | 0 | no | 0 | no | Codetext
 | H2 Ebene +3 | WA-LB | 1255Wa 0000000897 | yes | Codetext | m² | Trockenbauarbeiten | Wand | Außenwand 7-Schalig | WA-LB | 0 | A | 11.25 | 1255HWa0000000428 | NEW | no | yes | 0 | 0 | no | 0 | no | Codetext
 | H2 Ebene +3 | WA-DL | 1255Wa 0000002274 | yes | Codetext | m³ | Zimmer- und Holzbauarbeiten | Wand | Außenwand 7-Schalig | WA-DL | 0 | A | 11.25 | 1255HWa0000000428 | NEW | no | yes | 0 | 0 | no | 0 | no | Codetext
 | H2 Ebene +3 | WA-DL | 1255Wa 0000002290 | yes | Codetext | m³ | Zimmer- und Holzbauarbeiten | Wand | Außenwand 7-Schalig | WA-DL | 0 | A | 11.25 | 1255HWa0000000428 | NEW | no | yes | 0 | 0 | no | 0 | no | Codetext
 | H2 Ebene +3 | WA-LB | 1255Wa 0000002292 | yes | Codetext | m² | Trockenbauarbeiten | Wand | Außenwand 7-Schalig | WA-LB | 0 | A | 11.25 | 1255HWa0000000428 | NEW | no | yes | 0 | 0 | no | 0 | no | Codetext
 | H2 Ebene +3 | WA-KL | 1255Wa 0000002294 | yes | Codetext | m² | Zimmer- und Holzbauarbeiten | Wand | Außenwand 7-Schalig | WA-KL | 0 | A | 11.25 | 1255HWa0000000428 | NEW | no | yes | 0 | 0 | no | 0 | no | Codetext
 | H2 Ebene +3 | WA-TL | 1255Wa 0000002296 | yes | Codetext | m² | Zimmer- und Holzbauarbeiten | Wand | Außenwand 7-Schalig | WA-TL | 0 | A | 11.25 | 1255HWa0000000428 | NEW | no | yes | 0 | 0 | no | 0 | no | Codetext
 | H2 Ebene +3 | WA-HS | 1255Wa 0000002298 | yes | Codetext | m² | Zimmer- und Holzbauarbeiten | Wand | Außenwand 7-Schalig | WA-HS | 0 | A | 11.25 | 1255HWa0000000428 | NEW | no | yes | 0 | 0 | no | 0 | no | Codetext
 | H2 Ebene +3 | WA-LB | 1255Wa 0811524702 | yes | Codetext | m² | Trockenbauarbeiten | Wand | Außenwand 7-Schalig | WA-LB | 0 | A | 11.25 | 1255HWa0000000145 | NEW | no | yes | 0 | 0 | no | 0 | no | Codetext
 | H2 Ebene +3 | WA-DL | 1255Wa 0811524701 | yes | Codetext | m³ | Zimmer- und Holzbauarbeiten | Wand | Außenwand 7-Schalig | WA-DL | 0 | A | 11.25 | 1255HWa0000000145 | NEW | no | yes | 0 | 0 | no | 0 | no | Codetext
 | H2 Ebene +3 | WA-DL | 1255Wa 0811524700 | yes | Codetext | m³ | Zimmer- und Holzbauarbeiten | Wand | Außenwand 7-Schalig | WA-DL | 0 | A | 11.25 | 1255HWa0000000145 | NEW | no | yes | 0 | 0 | no | 0 | no | Codetext
 | H2 Ebene +3 | WA-DL | 1255Wa 0811524699 | yes | Codetext | m³ | Zimmer- und Holzbauarbeiten | Wand | Außenwand 7-Schalig | WA-DL | 0 | A | 11.25 | 1255HWa0000000145 | NEW | no | yes | 0 | 0 | no | 0 | no | Codetext
 | H2 Ebene +3 | WA-LB | 1255Wa 0811524698 | yes | Codetext | m² | Trockenbauarbeiten | Wand | Außenwand 7-Schalig | WA-LB | 0 | A | 11.25 | 1255HWa0000000145 | NEW | no | yes | 0 | 0 | no | 0 | no | Codetext
 | H2 Ebene +3 | WA-KL | 1255Wa 0811524697 | yes | Codetext | m² | Zimmer- und Holzbauarbeiten | Wand | Außenwand 7-Schalig | WA-KL | 0 | A | 11.25 | 1255HWa0000000145 | NEW | no | yes | 0 | 0 | no | 0 | no | Codetext
 | H2 Ebene +3 | WA-TL | 1255Wa 0811524696 | yes | Codetext | m² | Zimmer- und Holzbauarbeiten | Wand | Außenwand 7-Schalig | WA-TL | 0 | A | 11.25 | 1255HWa0000000145 | NEW | no | yes | 0 | 0 | no | 0 | no | Codetext
 | H2 Ebene +3 | WA-HS | 1255Wa 0811524695 | yes | Codetext | m² | Zimmer- und Holzbauarbeiten | Wand | Außenwand 7-Schalig | WA-HS | 0 | A | 11.25 | 1255HWa0000000145 | NEW | no | yes | 0 | 0 | no | 0 | no | Codetext
 | H2 Ebene +3 | WA-LB | 1255Wa 0000000843 | yes | Codetext | m² | Trockenbauarbeiten | Wand | Außenwand 7-Schalig | WA-LB | 0 | A | 11.25 | 1255HWa0000000145 | NEW | no | yes | 0 | 0 | no | 0 | no | Codetext
 | H2 Ebene +3 | WA-DL | 1255Wa 0000001556 | yes | Codetext | m³ | Zimmer- und Holzbauarbeiten | Wand | Außenwand 7-Schalig | WA-DL | 0 | A | 11.25 | 1255HWa0000000145 | NEW | no | yes | 0 | 0 | no | 0 | no | Codetext
 | H2 Ebene +3 | WA-DL | 1255Wa 0000001548 | yes | Codetext | m³ | Zimmer- und Holzbauarbeiten | Wand | Außenwand 7-Schalig | WA-DL | 0 | A | 11.25 | 1255HWa0000000145 | NEW | no | yes | 0 | 0 | no | 0 | no | Codetext
 | H2 Ebene +3 | WA-DL | 1255Wa 0000001540 | yes | Codetext | m³ | Zimmer- und Holzbauarbeiten | Wand | Außenwand 7-Schalig | WA-DL | 0 | A | 11.25 | 1255HWa0000000145 | NEW | no | yes | 0 | 0 | no | 0 | no | Codetext
 | H2 Ebene +3 | WA-LB | 1255Wa 0000001532 | yes | Codetext | m² | Trockenbauarbeiten | Wand | Außenwand 7-Schalig | WA-LB | 0 | A | 11.25 | 1255HWa0000000145 | NEW | no | yes | 0 | 0 | no | 0 | no | Codetext
 | H2 Ebene +3 | WA-KL | 1255Wa 0000001524 | yes | Codetext | m² | Zimmer- und Holzbauarbeiten | Wand | Außenwand 7-Schalig | WA-KL | 0 | A | 11.25 | 1255HWa0000000145 | NEW | no | yes | 0 | 0 | no | 0 | no | Codetext
 | H2 Ebene +3 | WA-TL | 1255Wa 0000001516 | yes | Codetext | m² | Zimmer- und Holzbauarbeiten | Wand | Außenwand 7-Schalig | WA-TL | 0 | A | 11.25 | 1255HWa0000000145 | NEW | no | yes | 0 | 0 | no | 0 | no | Codetext
 | H2 Ebene +3 | WA-HS | 1255Wa 0811474006 | yes | Codetext | m² | Zimmer- und Holzbauarbeiten | Wand | Außenwand 7-Schalig | WA-HS | 0 | A | 11.25 | 1255HWa0000000145 | NEW | no | yes | 0 | 0 | no | 0 | no | Codetext
2x Gipsfaserplatte | H2 Ebene +3 | WA-LB | 1255Wa 0811467463 | yes |  | m² | Trockenbauarbeiten | Wand | 2x Gipsfaserplatte | WA-LB |  |  | 11.25 | 1255HWa0811467393 | NEW | no | yes | REI 60-A1 - D,s2-d0 +A1
Holzständer + Zwischendämmung | H2 Ebene +3 | WA-HD | 1255Wa 0811467462 | yes |  | m³ | Zimmer- und Holzbauarbeiten | Wand | Holzständer + Zwischendämmung | WA-HD |  |  | 11.25 | 1255HWa0811467393 | NEW | no | yes | REI 60-A1 - D,s2-d0 +A1 | AllplanAttributes - ash D_Detailverweis: DT D; ash D_Plannummer: D1851
Staffel + Zwischendämmung | H2 Ebene +3 | WA-DL | 1255Wa 0811467461 | yes |  | m³ | Zimmer- und Holzbauarbeiten | Wand | Staffel + Zwischendämmung | WA-DL |  |  | 11.25 | 1255HWa0811467393 | NEW | no | yes | REI 60-A1 - D,s2-d0 +A1
 | H2 Ebene +3 | WA-LB | 1255Wa 0811467460 | yes | Codetext | m² | Trockenbauarbeiten | Wand | Außenwand 7-Schalig | WA-LB | 0 | A | 11.25 | 1255HWa0811467393 | NEW | no | yes | 0 | 0 | no | 0 | no | Codetext
Konterlattung | H2 Ebene +3 | WA-KL | 1255Wa 0811467459 | yes |  | m² | Zimmer- und Holzbauarbeiten | Wand | Konterlattung | WA-KL |  |  | 11.25 | 1255HWa0811467393 | NEW | no | yes | REI 60-A1 - D,s2-d0 +A1
Traglattung | H2 Ebene +3 | WA-TL | 1255Wa 0811467458 | yes |  | m² | Zimmer- und Holzbauarbeiten | Wand | Traglattung | WA-TL |  |  | 11.25 | 1255HWa0811467393 | NEW | no | yes | REI 60-A1 - D,s2-d0 +A1
Holzschindel | H2 Ebene +3 | WA-HS | 1255Wa 0811467457 | yes |  | m² | Zimmer- und Holzbauarbeiten | Wand | Holzschindel | WA-HS |  |  | 11.25 | 1255HWa0811467393 | NEW | no | yes | REI 60-A1 - D,s2-d0 +A1
2x Gipsfaserplatte | H2 Ebene +3 | WA-LB | 1255Wa 0000010634 | yes |  | m² | Trockenbauarbeiten | Wand | 2x Gipsfaserplatte | WA-LB |  |  | 11.25 | 1255HWa0000010612 | NEW | no | yes | REI 60-A1 - D,s2-d0 +A1
Holzständer + Zwischendämmung | H2 Ebene +3 | WA-HD | 1255Wa 0000010639 | yes |  | m³ | Zimmer- und Holzbauarbeiten | Wand | Holzständer + Zwischendämmung | WA-HD |  |  | 11.25 | 1255HWa0000010612 | NEW | no | yes | REI 60-A1 - D,s2-d0 +A1 | AllplanAttributes - ash D_Detailverweis: DT D; ash D_Plannummer: D1851
Staffel + Zwischendämmung | H2 Ebene +3 | WA-DL | 1255Wa 0000010638 | yes |  | m³ | Zimmer- und Holzbauarbeiten | Wand | Staffel + Zwischendämmung | WA-DL |  |  | 11.25 | 1255HWa0000010612 | NEW | no | yes | REI 60-A1 - D,s2-d0 +A1
 | H2 Ebene +3 | WA-LB | 1255Wa 0000010637 | yes | Codetext | m² | Trockenbauarbeiten | Wand | Außenwand 7-Schalig | WA-LB | 0 | A | 11.25 | 1255HWa0000010612 | NEW | no | yes | 0 | 0 | no | 0 | no | Codetext
Konterlattung | H2 Ebene +3 | WA-KL | 1255Wa 0000010636 | yes |  | m² | Zimmer- und Holzbauarbeiten | Wand | Konterlattung | WA-KL |  |  | 11.25 | 1255HWa0000010612 | NEW | no | yes | REI 60-A1 - D,s2-d0 +A1
Traglattung | H2 Ebene +3 | WA-TL | 1255Wa 0000010635 | yes |  | m² | Zimmer- und Holzbauarbeiten | Wand | Traglattung | WA-TL |  |  | 11.25 | 1255HWa0000010612 | NEW | no | yes | REI 60-A1 - D,s2-d0 +A1
2x Gipsfaserplatte | H2 Ebene +3 | WA-LB | 1255Wa 0811456485 | yes |  | m² | Trockenbauarbeiten | Wand | 2x Gipsfaserplatte | WA-LB |  |  | 11.25 | 1255HWa0811456429 | NEW | no | yes | REI 60-A1 - D,s2-d0 +A1
Holzständer + Zwischendämmung | H2 Ebene +3 | WA-HD | 1255Wa 0811456484 | yes |  | m³ | Zimmer- und Holzbauarbeiten | Wand | Holzständer + Zwischendämmung | WA-HD |  |  | 11.25 | 1255HWa0811456429 | NEW | no | yes | REI 60-A1 - D,s2-d0 +A1 | AllplanAttributes - ash D_Detailverweis: DT D; ash D_Plannummer: D1851
Staffel + Zwischendämmung | H2 Ebene +3 | WA-DL | 1255Wa 0811456483 | yes |  | m³ | Zimmer- und Holzbauarbeiten | Wand | Staffel + Zwischendämmung | WA-DL |  |  | 11.25 | 1255HWa0811456429 | NEW | no | yes | REI 60-A1 - D,s2-d0 +A1
 | H2 Ebene +3 | WA-LB | 1255Wa 0811456482 | yes | Codetext | m² | Trockenbauarbeiten | Wand | Außenwand 7-Schalig | WA-LB | 0 | A | 11.25 | 1255HWa0811456429 | NEW | no | yes | 0 | 0 | no | 0 | no | Codetext
Konterlattung | H2 Ebene +3 | WA-KL | 1255Wa 0811456481 | yes |  | m² | Zimmer- und Holzbauarbeiten | Wand | Konterlattung | WA-KL |  |  | 11.25 | 1255HWa0811456429 | NEW | no | yes | REI 60-A1 - D,s2-d0 +A1
Traglattung | H2 Ebene +3 | WA-TL | 1255Wa 0811456480 | yes |  | m² | Zimmer- und Holzbauarbeiten | Wand | Traglattung | WA-TL |  |  | 11.25 | 1255HWa0811456429 | NEW | no | yes | REI 60-A1 - D,s2-d0 +A1
Holzschindel | H2 Ebene +3 | WA-HS | 1255Wa 0811456479 | yes |  | m² | Zimmer- und Holzbauarbeiten | Wand | Holzschindel | WA-HS |  |  | 11.25 | 1255HWa0811456429 | NEW | no | yes | REI 60-A1 - D,s2-d0 +A1
 | H2 Ebene +3 | WA-LB | 1255Wa 0000001668 | yes | Codetext | m² | Trockenbauarbeiten | Wand | Außenwand 7-Schalig | WA-LB | 0 | A | 11.25 | 1255HWa0000001424 | NEW | no | yes | 0 | 0 | no | 0 | no | Codetext
 | H2 Ebene +3 | WA-DL | 1255Wa 0000001664 | yes | Codetext | m³ | Zimmer- und Holzbauarbeiten | Wand | Außenwand 7-Schalig | WA-DL | 0 | A | 11.25 | 1255HWa0000001424 | NEW | no | yes | 0 | 0 | no | 0 | no | Codetext | AllplanAttributes - ash D_Detailverweis: DT D; ash D_Plannummer: D1851
 | H2 Ebene +3 | WA-DL | 1255Wa 0000001660 | yes | Codetext | m³ | Zimmer- und Holzbauarbeiten | Wand | Außenwand 7-Schalig | WA-DL | 0 | A | 11.25 | 1255HWa0000001424 | NEW | no | yes | 0 | 0 | no | 0 | no | Codetext
 | H2 Ebene +3 | WA-LB | 1255Wa 0000001656 | yes | Codetext | m² | Trockenbauarbeiten | Wand | Außenwand 7-Schalig | WA-LB | 0 | A | 11.25 | 1255HWa0000001424 | NEW | no | yes | 0 | 0 | no | 0 | no | Codetext
 | H2 Ebene +3 | WA-KL | 1255Wa 0000001652 | yes | Codetext | m² | Zimmer- und Holzbauarbeiten | Wand | Außenwand 7-Schalig | WA-KL | 0 | A | 11.25 | 1255HWa0000001424 | NEW | no | yes | 0 | 0 | no | 0 | no | Codetext
 | H2 Ebene +3 | WA-TL | 1255Wa 0000001648 | yes | Codetext | m² | Zimmer- und Holzbauarbeiten | Wand | Außenwand 7-Schalig | WA-TL | 0 | A | 11.25 | 1255HWa0000001424 | NEW | no | yes | 0 | 0 | no | 0 | no | Codetext
 | H2 Ebene +3 | WA-HS | 1255Wa 0000001644 | yes | Codetext | m² | Zimmer- und Holzbauarbeiten | Wand | Außenwand 7-Schalig | WA-HS | 0 | A | 11.25 | 1255HWa0000001424 | NEW | no | yes | 0 | 0 | no | 0 | no | Codetext
2x Gipsfaserplatte | H2 Ebene +3 | WA-LB | 1255Wa 0000001719 | yes |  | m² | Trockenbauarbeiten | Wand | 2x Gipsfaserplatte | WA-LB |  |  | 11.25 | 1255HWa0000001627 | NEW | no | yes | REI 60-A1 - D,s2-d0 +A1
Holzständer + Zwischendämmung | H2 Ebene +3 | WA-HD | 1255Wa 0000001630 | yes |  | m³ | Zimmer- und Holzbauarbeiten | Wand | Holzständer + Zwischendämmung | WA-HD |  |  | 11.25 | 1255HWa0000001627 | NEW | no | yes | REI 60-A1 - D,s2-d0 +A1
Staffel + Zwischendämmung | H2 Ebene +3 | WA-DL | 1255Wa 0000001632 | yes |  | m³ | Zimmer- und Holzbauarbeiten | Wand | Staffel + Zwischendämmung | WA-DL |  |  | 11.25 | 1255HWa0000001627 | NEW | no | yes | REI 60-A1 - D,s2-d0 +A1
 | H2 Ebene +3 | WA-LB | 1255Wa 0000001634 | yes | Codetext | m² | Trockenbauarbeiten | Wand | Außenwand 7-Schalig | WA-LB | 0 | A | 11.25 | 1255HWa0000001627 | NEW | no | yes | 0 | 0 | no | 0 | no | Codetext
Konterlattung | H2 Ebene +3 | WA-KL | 1255Wa 0000001636 | yes |  | m² | Zimmer- und Holzbauarbeiten | Wand | Konterlattung | WA-KL |  |  | 11.25 | 1255HWa0000001627 | NEW | no | yes | REI 60-A1 - D,s2-d0 +A1
Traglattung | H2 Ebene +3 | WA-TL | 1255Wa 0000001638 | yes |  | m² | Zimmer- und Holzbauarbeiten | Wand | Traglattung | WA-TL |  |  | 11.25 | 1255HWa0000001627 | NEW | no | yes | REI 60-A1 - D,s2-d0 +A1
Holzschindel | H2 Ebene +3 | WA-HS | 1255Wa 0000001640 | yes |  | m² | Zimmer- und Holzbauarbeiten | Wand | Holzschindel | WA-HS |  |  | 11.25 | 1255HWa0000001627 | NEW | no | yes | REI 60-A1 - D,s2-d0 +A1
 | H2 Ebene +3 | WA-LB | 1255Wa 0811546429 | yes | Codetext | m² | Trockenbauarbeiten | Wand | Außenwand 7-Schalig | WA-LB | 0 | A | 11.25 | 1255HWa0000001569 | NEW | no | yes | 0 | 0 | no | 0 | no | Codetext
 | H2 Ebene +3 | WA-DL | 1255Wa 0811546428 | yes | Codetext | m³ | Zimmer- und Holzbauarbeiten | Wand | Außenwand 7-Schalig | WA-DL | 0 | A | 11.25 | 1255HWa0000001569 | NEW | no | yes | 0 | 0 | no | 0 | no | Codetext
 | H2 Ebene +3 | WA-DL | 1255Wa 0811546427 | yes | Codetext | m³ | Zimmer- und Holzbauarbeiten | Wand | Außenwand 7-Schalig | WA-DL | 0 | A | 11.25 | 1255HWa0000001569 | NEW | no | yes | 0 | 0 | no | 0 | no | Codetext
 | H2 Ebene +3 | WA-LB | 1255Wa 0811546426 | yes | Codetext | m² | Trockenbauarbeiten | Wand | Außenwand 7-Schalig | WA-LB | 0 | A | 11.25 | 1255HWa0000001569 | NEW | no | yes | 0 | 0 | no | 0 | no | Codetext
 | H2 Ebene +3 | WA-KL | 1255Wa 0811546425 | yes | Codetext | m² | Zimmer- und Holzbauarbeiten | Wand | Außenwand 7-Schalig | WA-KL | 0 | A | 11.25 | 1255HWa0000001569 | NEW | no | yes | 0 | 0 | no | 0 | no | Codetext
 | H2 Ebene +3 | WA-TL | 1255Wa 0811546424 | yes | Codetext | m² | Zimmer- und Holzbauarbeiten | Wand | Außenwand 7-Schalig | WA-TL | 0 | A | 11.25 | 1255HWa0000001569 | NEW | no | yes | 0 | 0 | no | 0 | no | Codetext
 | H2 Ebene +3 | WA-HS | 1255Wa 0811546423 | yes | Codetext | m² | Zimmer- und Holzbauarbeiten | Wand | Außenwand 7-Schalig | WA-HS | 0 | A | 11.25 | 1255HWa0000001569 | NEW | no | yes | 0 | 0 | no | 0 | no | Codetext
2x Gipsfaserplatte | H2 Ebene +3 | WA-LB | 1255Wa 0000015121 | yes |  | m² | Trockenbauarbeiten | Wand | 2x Gipsfaserplatte | WA-LB |  |  | 11.25 | 1255HWa0000015120 | NEW | no | yes | REI 60-A1 - D,s2-d0 +A1
Holzständer + Zwischendämmung | H2 Ebene +3 | WA-HD | 1255Wa 0000015122 | yes |  | m³ | Zimmer- und Holzbauarbeiten | Wand | Holzständer + Zwischendämmung | WA-HD |  |  | 11.25 | 1255HWa0000015120 | NEW | no | yes | REI 60-A1 - D,s2-d0 +A1
Staffel + Zwischendämmung | H2 Ebene +3 | WA-DL | 1255Wa 0000015123 | yes |  | m³ | Zimmer- und Holzbauarbeiten | Wand | Staffel + Zwischendämmung | WA-DL |  |  | 11.25 | 1255HWa0000015120 | NEW | no | yes | REI 60-A1 - D,s2-d0 +A1
 | H2 Ebene +3 | WA-LB | 1255Wa 0000015124 | yes | Codetext | m² | Trockenbauarbeiten | Wand | Außenwand 7-Schalig | WA-LB | 0 | A | 11.25 | 1255HWa0000015120 | NEW | no | yes | 0 | 0 | no | 0 | no | Codetext
Konterlattung | H2 Ebene +3 | WA-KL | 1255Wa 0000015125 | yes |  | m² | Zimmer- und Holzbauarbeiten | Wand | Konterlattung | WA-KL |  |  | 11.25 | 1255HWa0000015120 | NEW | no | yes | REI 60-A1 - D,s2-d0 +A1
Traglattung | H2 Ebene +3 | WA-TL | 1255Wa 0000015126 | yes |  | m² | Zimmer- und Holzbauarbeiten | Wand | Traglattung | WA-TL |  |  | 11.25 | 1255HWa0000015120 | NEW | no | yes | REI 60-A1 - D,s2-d0 +A1
Holzschindel | H2 Ebene +3 | WA-HS | 1255Wa 0000015127 | yes |  | m² | Zimmer- und Holzbauarbeiten | Wand | Holzschindel | WA-HS |  |  | 11.25 | 1255HWa0000015120 | NEW | no | yes | REI 60-A1 - D,s2-d0 +A1
 | H2 Ebene +3 | WA-LB | 1255Wa 0000015159 | yes | Codetext | m² | Trockenbauarbeiten | Wand | Außenwand 7-Schalig | WA-LB | 0 | A | 11.25 | 1255HWa0000015158 | NEW | no | yes | 0 | 0 | no | 0 | no | Codetext
 | H2 Ebene +3 | WA-DL | 1255Wa 0000015160 | yes | Codetext | m³ | Zimmer- und Holzbauarbeiten | Wand | Außenwand 7-Schalig | WA-DL | 0 | A | 11.25 | 1255HWa0000015158 | NEW | no | yes | 0 | 0 | no | 0 | no | Codetext | AllplanAttributes - ash D_Detailverweis: DT D; ash D_Plannummer: D1851
 | H2 Ebene +3 | WA-DL | 1255Wa 0000015161 | yes | Codetext | m³ | Zimmer- und Holzbauarbeiten | Wand | Außenwand 7-Schalig | WA-DL | 0 | A | 11.25 | 1255HWa0000015158 | NEW | no | yes | 0 | 0 | no | 0 | no | Codetext
 | H2 Ebene +3 | WA-LB | 1255Wa 0000015162 | yes | Codetext | m² | Trockenbauarbeiten | Wand | Außenwand 7-Schalig | WA-LB | 0 | A | 11.25 | 1255HWa0000015158 | NEW | no | yes | 0 | 0 | no | 0 | no | Codetext
 | H2 Ebene +3 | WA-KL | 1255Wa 0000015163 | yes | Codetext | m² | Zimmer- und Holzbauarbeiten | Wand | Außenwand 7-Schalig | WA-KL | 0 | A | 11.25 | 1255HWa0000015158 | NEW | no | yes | 0 | 0 | no | 0 | no | Codetext
 | H2 Ebene +3 | WA-TL | 1255Wa 0000015164 | yes | Codetext | m² | Zimmer- und Holzbauarbeiten | Wand | Außenwand 7-Schalig | WA-TL | 0 | A | 11.25 | 1255HWa0000015158 | NEW | no | yes | 0 | 0 | no | 0 | no | Codetext
 | H2 Ebene +3 | WA-HS | 1255Wa 0000015165 | yes | Codetext | m² | Zimmer- und Holzbauarbeiten | Wand | Außenwand 7-Schalig | WA-HS | 0 | A | 11.25 | 1255HWa0000015158 | NEW | no | yes | 0 | 0 | no | 0 | no | Codetext
 | H2 Ebene +3 | WA-LB | 1255Wa 0000001596 | yes | Codetext | m² | Trockenbauarbeiten | Wand | Außenwand 7-Schalig | WA-LB | 0 | A | 11.25 | 1255HWa0000000216 | NEW | no | yes | 0 | 0 | no | 0 | no | Codetext
 | H2 Ebene +3 | WA-DL | 1255Wa 0000001601 | yes | Codetext | m³ | Zimmer- und Holzbauarbeiten | Wand | Außenwand 7-Schalig | WA-DL | 0 | A | 11.25 | 1255HWa0000000216 | NEW | no | yes | 0 | 0 | no | 0 | no | Codetext | AllplanAttributes - ash D_Detailverweis: DT D; ash D_Plannummer: D1851
 | H2 Ebene +3 | WA-DL | 1255Wa 0000001606 | yes | Codetext | m³ | Zimmer- und Holzbauarbeiten | Wand | Außenwand 7-Schalig | WA-DL | 0 | A | 11.25 | 1255HWa0000000216 | NEW | no | yes | 0 | 0 | no | 0 | no | Codetext
 | H2 Ebene +3 | WA-LB | 1255Wa 0000001611 | yes | Codetext | m² | Trockenbauarbeiten | Wand | Außenwand 7-Schalig | WA-LB | 0 | A | 11.25 | 1255HWa0000000216 | NEW | no | yes | 0 | 0 | no | 0 | no | Codetext
 | H2 Ebene +3 | WA-KL | 1255Wa 0000001616 | yes | Codetext | m² | Zimmer- und Holzbauarbeiten | Wand | Außenwand 7-Schalig | WA-KL | 0 | A | 11.25 | 1255HWa0000000216 | NEW | no | yes | 0 | 0 | no | 0 | no | Codetext
 | H2 Ebene +3 | WA-TL | 1255Wa 0000001621 | yes | Codetext | m² | Zimmer- und Holzbauarbeiten | Wand | Außenwand 7-Schalig | WA-TL | 0 | A | 11.25 | 1255HWa0000000216 | NEW | no | yes | 0 | 0 | no | 0 | no | Codetext
 | H2 Ebene +3 | WA-HS | 1255Wa 0000001626 | yes | Codetext | m² | Zimmer- und Holzbauarbeiten | Wand | Außenwand 7-Schalig | WA-HS | 0 | A | 11.25 | 1255HWa0000000216 | NEW | no | yes | 0 | 0 | no | 0 | no | Codetext
 | H2 Ebene +3 | WA-LB | 1255Wa 0000001179 | yes | Codetext | m² | Trockenbauarbeiten | Wand | Außenwand 7-Schalig | WA-LB | 0 | A | 11.25 | 1255HWa0000000076 | NEW | no | yes | 0 | 0 | no | 0 | no | Codetext
 | H2 Ebene +3 | WA-DL | 1255Wa 0000001191 | yes | Codetext | m³ | Zimmer- und Holzbauarbeiten | Wand | Außenwand 7-Schalig | WA-DL | 0 | A | 11.25 | 1255HWa0000000076 | NEW | no | yes | 0 | 0 | no | 0 | no | Codetext
 | H2 Ebene +3 | WA-DL | 1255Wa 0000001189 | yes | Codetext | m³ | Zimmer- und Holzbauarbeiten | Wand | Außenwand 7-Schalig | WA-DL | 0 | A | 11.25 | 1255HWa0000000076 | NEW | no | yes | 0 | 0 | no | 0 | no | Codetext
 | H2 Ebene +3 | WA-LB | 1255Wa 0000001187 | yes | Codetext | m² | Trockenbauarbeiten | Wand | Außenwand 7-Schalig | WA-LB | 0 | A | 11.25 | 1255HWa0000000076 | NEW | no | yes | 0 | 0 | no | 0 | no | Codetext
 | H2 Ebene +3 | WA-KL | 1255Wa 0000001185 | yes | Codetext | m² | Zimmer- und Holzbauarbeiten | Wand | Außenwand 7-Schalig | WA-KL | 0 | A | 11.25 | 1255HWa0000000076 | NEW | no | yes | 0 | 0 | no | 0 | no | Codetext
 | H2 Ebene +3 | WA-TL | 1255Wa 0000001183 | yes | Codetext | m² | Zimmer- und Holzbauarbeiten | Wand | Außenwand 7-Schalig | WA-TL | 0 | A | 11.25 | 1255HWa0000000076 | NEW | no | yes | 0 | 0 | no | 0 | no | Codetext
 | H2 Ebene +3 | WA-HS | 1255Wa 0000001181 | yes | Codetext | m² | Zimmer- und Holzbauarbeiten | Wand | Außenwand 7-Schalig | WA-HS | 0 | A | 11.25 | 1255HWa0000000076 | NEW | no | yes | 0 | 0 | no | 0 | no | Codetext
2x Gipsfaserplatte | H2 Ebene +3 | WA-LB | 1255Wa 0811453991 | yes |  | m² | Trockenbauarbeiten | Wand | 2x Gipsfaserplatte | WA-LB |  |  | 11.25 | 1255HWa0811453981 | NEW | no | yes | REI 60-A1 - D,s2-d0 +A1
2x Gipsfaserplatte | H2 Ebene +3 | WA-LB | 1255Wa 0811453990 | yes |  | m² | Trockenbauarbeiten | Wand | 2x Gipsfaserplatte | WA-LB |  |  | 11.25 | 1255HWa0811453981 | NEW | no | yes | 0 | 0.9 |  | 32 | AllplanAttributes - Sicherheitsklasse: -; Sonnenschutztyp: Movable; g-Wert: 0,51
Holzständer + Zwischendämmung | H2 Ebene +3 | WA-HD | 1255Wa 0811453989 | yes |  | m³ | Zimmer- und Holzbauarbeiten | Wand | Holzständer + Zwischendämmung | WA-HD |  |  | 11.25 | 1255HWa0811453981 | NEW | no | yes | REI 60-A1 - D,s2-d0 +A1 | AllplanAttributes - ash D_Detailverweis: DT 7; ash D_Plannummer: D1614
Staffel + Zwischendämmung | H2 Ebene +3 | WA-DL | 1255Wa 0811453988 | yes |  | m³ | Zimmer- und Holzbauarbeiten | Wand | Staffel + Zwischendämmung | WA-DL |  |  | 11.25 | 1255HWa0811453981 | NEW | no | yes | REI 60-A1 - D,s2-d0 +A1
 | H2 Ebene +3 | WA-LB | 1255Wa 0811453987 | yes | Codetext | m² | Trockenbauarbeiten | Wand | Außenwand 7-Schalig | WA-LB | 0 | A | 11.25 | 1255HWa0811453981 | NEW | no | yes | 0 | 0.9 | no | 32 | no | Codetext | AllplanAttributes - Sicherheitsklasse: -; Sonnenschutztyp: Movable; g-Wert: 0,51
 | H2 Ebene +3 | WA-LB | 1255Wa 0811453986 | yes | Codetext | m² | Trockenbauarbeiten | Wand | Außenwand 7-Schalig | WA-LB | 0 | A | 11.25 | 1255HWa0811453981 | NEW | no | yes | 0 | 0 | no | 0 | no | Codetext
Konterlattung | H2 Ebene +3 | WA-KL | 1255Wa 0811453985 | yes |  | m² | Zimmer- und Holzbauarbeiten | Wand | Konterlattung | WA-KL |  |  | 11.25 | 1255HWa0811453981 | NEW | no | yes | REI 60-A1 - D,s2-d0 +A1
Traglattung | H2 Ebene +3 | WA-TL | 1255Wa 0811453984 | yes |  | m² | Zimmer- und Holzbauarbeiten | Wand | Traglattung | WA-TL |  |  | 11.25 | 1255HWa0811453981 | NEW | no | yes | REI 60-A1 - D,s2-d0 +A1
Holzschindel | H2 Ebene +3 | WA-HS | 1255Wa 0811453983 | yes |  | m² | Zimmer- und Holzbauarbeiten | Wand | Holzschindel | WA-HS |  |  | 11.25 | 1255HWa0811453981 | NEW | no | yes | REI 60-A1 - D,s2-d0 +A1
 | H2 Ebene +3 | WA-LB | 1255Wa 0000001561 | yes | Codetext | m² | Trockenbauarbeiten | Wand | Außenwand 7-Schalig | WA-LB | 0 | A | 11.25 | 1255HWa0000000192 | NEW | no | yes | 0 | 0 | no | 0 | no | Codetext
 | H2 Ebene +3 | WA-DL | 1255Wa 0000001492 | yes | Codetext | m³ | Zimmer- und Holzbauarbeiten | Wand | Außenwand 7-Schalig | WA-DL | 0 | A | 11.25 | 1255HWa0000000192 | NEW | no | yes | 0 | 0 | no | 0 | no | Codetext
 | H2 Ebene +3 | WA-DL | 1255Wa 0000001496 | yes | Codetext | m³ | Zimmer- und Holzbauarbeiten | Wand | Außenwand 7-Schalig | WA-DL | 0 | A | 11.25 | 1255HWa0000000192 | NEW | no | yes | 0 | 0 | no | 0 | no | Codetext
 | H2 Ebene +3 | WA-LB | 1255Wa 0000001500 | yes | Codetext | m² | Trockenbauarbeiten | Wand | Außenwand 7-Schalig | WA-LB | 0 | A | 11.25 | 1255HWa0000000192 | NEW | no | yes | 0 | 0 | no | 0 | no | Codetext
 | H2 Ebene +3 | WA-KL | 1255Wa 0000001504 | yes | Codetext | m² | Zimmer- und Holzbauarbeiten | Wand | Außenwand 7-Schalig | WA-KL | 0 | A | 11.25 | 1255HWa0000000192 | NEW | no | yes | 0 | 0 | no | 0 | no | Codetext
 | H2 Ebene +3 | WA-TL | 1255Wa 0000001508 | yes | Codetext | m² | Zimmer- und Holzbauarbeiten | Wand | Außenwand 7-Schalig | WA-TL | 0 | A | 11.25 | 1255HWa0000000192 | NEW | no | yes | 0 | 0 | no | 0 | no | Codetext
 | H2 Ebene +3 | WA-HS | 1255Wa 0000001488 | yes | Codetext | m² | Zimmer- und Holzbauarbeiten | Wand | Außenwand 7-Schalig | WA-HS | 0 | A | 11.25 | 1255HWa0000000192 | NEW | no | yes | 0 | 0 | no | 0 | no | Codetext
2x Gipsfaserplatte | H2 Ebene +3 | WA-LB | 1255Wa 0000006036 | yes |  | m² | Trockenbauarbeiten | Wand | 2x Gipsfaserplatte | WA-LB |  |  | 11.25 | 1255HWa0000006006 | NEW | no | yes | REI 60-A1 - D,s2-d0 +A1
Holzständer + Zwischendämmung | H2 Ebene +3 | WA-HD | 1255Wa 0000006035 | yes |  | m³ | Zimmer- und Holzbauarbeiten | Wand | Holzständer + Zwischendämmung | WA-HD |  |  | 11.25 | 1255HWa0000006006 | NEW | no | yes | REI 60-A1 - D,s2-d0 +A1 | AllplanAttributes - ash D_Detailverweis: DT D; ash D_Plannummer: D1851
Staffel + Zwischendämmung | H2 Ebene +3 | WA-DL | 1255Wa 0000006034 | yes |  | m³ | Zimmer- und Holzbauarbeiten | Wand | Staffel + Zwischendämmung | WA-DL |  |  | 11.25 | 1255HWa0000006006 | NEW | no | yes | REI 60-A1 - D,s2-d0 +A1
 | H2 Ebene +3 | WA-LB | 1255Wa 0000006033 | yes | Codetext | m² | Trockenbauarbeiten | Wand | Außenwand 7-Schalig | WA-LB | 0 | A | 11.25 | 1255HWa0000006006 | NEW | no | yes | 0 | 0 | no | 0 | no | Codetext
Konterlattung | H2 Ebene +3 | WA-KL | 1255Wa 0000006032 | yes |  | m² | Zimmer- und Holzbauarbeiten | Wand | Konterlattung | WA-KL |  |  | 11.25 | 1255HWa0000006006 | NEW | no | yes | REI 60-A1 - D,s2-d0 +A1
Traglattung | H2 Ebene +3 | WA-TL | 1255Wa 0000006031 | yes |  | m² | Zimmer- und Holzbauarbeiten | Wand | Traglattung | WA-TL |  |  | 11.25 | 1255HWa0000006006 | NEW | no | yes | REI 60-A1 - D,s2-d0 +A1
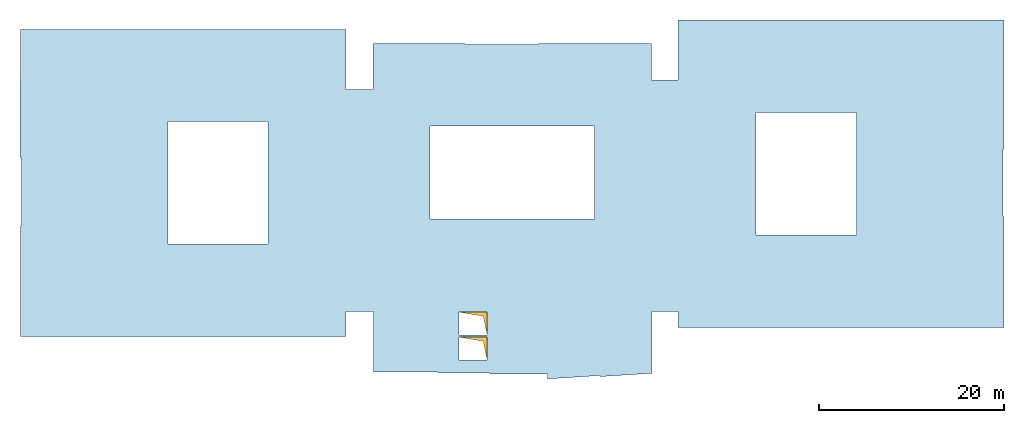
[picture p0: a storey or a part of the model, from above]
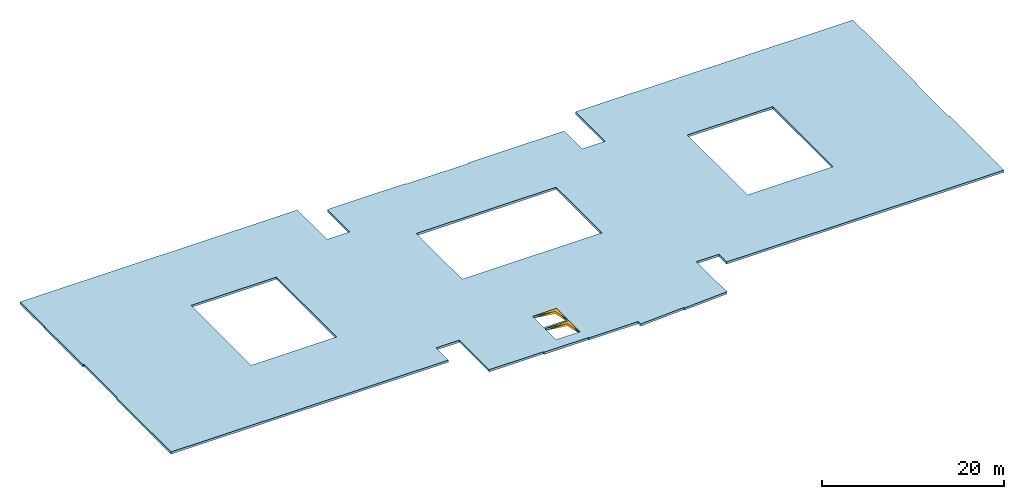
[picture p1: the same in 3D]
Properties of the parts of a building model (IFC4), part 46 of 80

# IfcWall (6826)
Name | In | Material | Allright_Bauteil_ID | 2D Interaktion | Codetext | Abrechnungsart | Gewerk | Objektname | Bezeichnung | AllplanAttributes, Material | Typ = SurfaceSpreadOfFlame | Brandschutzklasse | OKFF | P_ID | Status | LoadBearing | IsExternal | FireRating | ThermalTransmittance (W/K/m2) | Combustible | AcousticRating | Compartmentation | Reference
Holzschindel | H2 Ebene +3 | WA-HS | 1255Wa 0000006037 | yes |  | m² | Zimmer- und Holzbauarbeiten | Wand | Holzschindel | WA-HS |  |  | 11.25 | 1255HWa0000006006 | NEW | no | yes | REI 60-A1 - D,s2-d0 +A1
2x Gipsfaserplatte | H2 Ebene +3 | WA-LB | 1255Wa 0000004586 | yes |  | m² | Trockenbauarbeiten | Wand | 2x Gipsfaserplatte | WA-LB |  |  | 11.25 | 1255HWa0000004568 | NEW | no | yes | REI 60-A1 - D,s2-d0 +A1
Holzständer + Zwischendämmung | H2 Ebene +3 | WA-HD | 1255Wa 0000004584 | yes |  | m³ | Zimmer- und Holzbauarbeiten | Wand | Holzständer + Zwischendämmung | WA-HD |  |  | 11.25 | 1255HWa0000004568 | NEW | no | yes | REI 60-A1 - D,s2-d0 +A1
Staffel + Zwischendämmung | H2 Ebene +3 | WA-DL | 1255Wa 0000004582 | yes |  | m³ | Zimmer- und Holzbauarbeiten | Wand | Staffel + Zwischendämmung | WA-DL |  |  | 11.25 | 1255HWa0000004568 | NEW | no | yes | REI 60-A1 - D,s2-d0 +A1
 | H2 Ebene +3 | WA-LB | 1255Wa 0000004580 | yes | Codetext | m² | Trockenbauarbeiten | Wand | Außenwand 7-Schalig | WA-LB | 0 | A | 11.25 | 1255HWa0000004568 | NEW | no | yes | 0 | 0 | no | 0 | no | Codetext
Konterlattung | H2 Ebene +3 | WA-KL | 1255Wa 0000004578 | yes |  | m² | Zimmer- und Holzbauarbeiten | Wand | Konterlattung | WA-KL |  |  | 11.25 | 1255HWa0000004568 | NEW | no | yes | REI 60-A1 - D,s2-d0 +A1
Traglattung | H2 Ebene +3 | WA-TL | 1255Wa 0000004574 | yes |  | m² | Zimmer- und Holzbauarbeiten | Wand | Traglattung | WA-TL |  |  | 11.25 | 1255HWa0000004568 | NEW | no | yes | REI 60-A1 - D,s2-d0 +A1
Holzschindel | H2 Ebene +3 | WA-HS | 1255Wa 0000004571 | yes |  | m² | Zimmer- und Holzbauarbeiten | Wand | Holzschindel | WA-HS |  |  | 11.25 | 1255HWa0000004568 | NEW | no | yes | REI 60-A1 - D,s2-d0 +A1
 | H2 Ebene +3 | WA-DL | 1255Wa 0811554915 | yes | Codetext | m³ | Zimmer- und Holzbauarbeiten | Wand | Attika | WA-DL |  | A |  |  | NEW | no | yes |  | 0 | no |  | no | Codetext
Dämmung | H2 Ebene +3 | WA-DL | 1255Wa 0811554916 | yes | Codetext | m² | Zimmer- und Holzbauarbeiten | Wand | Dämmung | WA-DL |  | A |  |  | NEW | no | yes |  | 0 | no |  | no | Codetext
Dämmung | H2 Ebene +3 | WA-DL | 1255Wa 0811554917 | yes | Codetext | m² | Zimmer- und Holzbauarbeiten | Wand | Dämmung | WA-DL |  | A |  |  | NEW | no | yes |  | 0 | no |  | no | Codetext
Fassadenschicht (außen) | H2 Ebene +3 | WA-F | 1255Wa 0811554918 | yes | Codetext | m² | Zimmer- und Holzbauarbeiten | Wand | Fassadenschicht (außen) | WA-F |  | A |  |  | NEW | no | yes |  | 0 | no |  | no | Codetext
2x Gipsfaserplatte | H2 Ebene +3 | WA-LB | 1255Wa 0811467781 | yes |  | m² | Trockenbauarbeiten | Wand | 2x Gipsfaserplatte | WA-LB |  |  | 11.25 | 1255HWa0811467779 | NEW | no | yes | REI 60-A1 - D,s2-d0 +A1
Holzständer + Zwischendämmung | H2 Ebene +3 | WA-HD | 1255Wa 0811467782 | yes |  | m³ | Zimmer- und Holzbauarbeiten | Wand | Holzständer + Zwischendämmung | WA-HD |  |  | 11.25 | 1255HWa0811467779 | NEW | no | yes | REI 60-A1 - D,s2-d0 +A1
Staffel + Zwischendämmung | H2 Ebene +3 | WA-DL | 1255Wa 0811467783 | yes |  | m³ | Zimmer- und Holzbauarbeiten | Wand | Staffel + Zwischendämmung | WA-DL |  |  | 11.25 | 1255HWa0811467779 | NEW | no | yes | REI 60-A1 - D,s2-d0 +A1
 | H2 Ebene +3 | WA-LB | 1255Wa 0811467784 | yes | Codetext | m² | Trockenbauarbeiten | Wand | Außenwand 7-Schalig | WA-LB | 0 | A | 11.25 | 1255HWa0811467779 | NEW | no | yes | 0 | 0 | no | 0 | no | Codetext
Konterlattung | H2 Ebene +3 | WA-KL | 1255Wa 0811467785 | yes |  | m² | Zimmer- und Holzbauarbeiten | Wand | Konterlattung | WA-KL |  |  | 11.25 | 1255HWa0811467779 | NEW | no | yes | REI 60-A1 - D,s2-d0 +A1
Traglattung | H2 Ebene +3 | WA-TL | 1255Wa 0811467786 | yes |  | m² | Zimmer- und Holzbauarbeiten | Wand | Traglattung | WA-TL |  |  | 11.25 | 1255HWa0811467779 | NEW | no | yes | REI 60-A1 - D,s2-d0 +A1
Holzschindel | H2 Ebene +3 | WA-HS | 1255Wa 0811467787 | yes |  | m² | Zimmer- und Holzbauarbeiten | Wand | Holzschindel | WA-HS |  |  | 11.25 | 1255HWa0811467779 | NEW | no | yes | REI 60-A1 - D,s2-d0 +A1
 | H2 Ebene +3 | WA-DL | 1255Wa 0811557304 | yes | Codetext | m³ | Zimmer- und Holzbauarbeiten | Wand | Attika | WA-DL |  | A |  |  | NEW | no | yes |  | 0 | no |  | no | Codetext
Dämmung | H2 Ebene +3 | WA-DL | 1255Wa 0811557305 | yes | Codetext | m² | Zimmer- und Holzbauarbeiten | Wand | Dämmung | WA-DL |  | A |  |  | NEW | no | yes |  | 0 | no |  | no | Codetext
Dämmung | H2 Ebene +3 | WA-DL | 1255Wa 0811557306 | yes | Codetext | m² | Zimmer- und Holzbauarbeiten | Wand | Dämmung | WA-DL |  | A |  |  | NEW | no | yes |  | 0 | no |  | no | Codetext
Fassadenschicht (außen) | H2 Ebene +3 | WA-F | 1255Wa 0811557307 | yes | Codetext | m² | Zimmer- und Holzbauarbeiten | Wand | Fassadenschicht (außen) | WA-F |  | A |  |  | NEW | no | yes |  | 0 | no |  | no | Codetext
 | H2 Ebene +3 | WA-LB | 1255Wa 0811558782 | yes | Codetext | m² | Trockenbauarbeiten | Wand | Außenwand 7-Schalig | WA-LB | 0 | A | 11.25 | 1255HWa0811466406 | NEW | no | yes | REI 60-A1 - D,s2-d0 +A1 | 0 | no | 0 | no | Codetext
 | H2 Ebene +3 | WA-HD | 1255Wa 0811558783 | yes | Codetext | m³ | Zimmer- und Holzbauarbeiten | Wand | Außenwand 7-Schalig | WA-HD | 0 | A | 11.25 | 1255HWa0811466406 | NEW | yes | yes | REI 60-A1 - D,s2-d0 +A1 | 0 | no | 0 | no | Codetext
 | H2 Ebene +3 | WA-DL | 1255Wa 0811558784 | yes | Codetext | m³ | Zimmer- und Holzbauarbeiten | Wand | Außenwand 7-Schalig | WA-DL | 0 | A | 11.25 | 1255HWa0811466406 | NEW | no | yes | REI 60-A1 - D,s2-d0 +A1 | 0 | no | 0 | no | Codetext
 | H2 Ebene +3 | WA-LB | 1255Wa 0811558785 | yes | Codetext | m² | Trockenbauarbeiten | Wand | Außenwand 7-Schalig | WA-LB | 0 | A | 11.25 | 1255HWa0811456429 | NEW | no | yes | 0 | 0 | no | 0 | no | Codetext
 | H2 Ebene +3 | WA-KL | 1255Wa 0811558786 | yes | Codetext | m² | Zimmer- und Holzbauarbeiten | Wand | Außenwand 7-Schalig | WA-KL | 0 | A | 11.25 | 1255HWa0811466406 | NEW | no | yes | REI 60-A1 - D,s2-d0 +A1 | 0 | no | 0 | no | Codetext
 | H2 Ebene +3 | WA-TL | 1255Wa 0811558787 | yes | Codetext | m² | Zimmer- und Holzbauarbeiten | Wand | Außenwand 7-Schalig | WA-TL | 0 | A | 11.25 | 1255HWa0811466406 | NEW | no | yes | REI 60-A1 - D,s2-d0 +A1 | 0 | no | 0 | no | Codetext
 | H2 Ebene +3 | WA-HS | 1255Wa 0811558788 | yes | Codetext | m² | Zimmer- und Holzbauarbeiten | Wand | Außenwand 7-Schalig | WA-HS | 0 | A | 11.25 | 1255HWa0811466406 | NEW | no | yes | REI 60-A1 - D,s2-d0 +A1 | 0 | no | 0 | no | Codetext
 | H2 Ebene +3 | WA-LB | 1255Wa 0811467923 | yes | Codetext | m² | Trockenbauarbeiten | Wand | Außenwand 7-Schalig | WA-LB | 0 | A | 11.25 | 1255HWa0811467921 | NEW | no | yes | REI 60-A1 - D,s2-d0 +A1 | 0 | no | 0 | no | Codetext
 | H2 Ebene +3 | WA-HD | 1255Wa 0811467924 | yes | Codetext | m³ | Zimmer- und Holzbauarbeiten | Wand | Außenwand 7-Schalig | WA-HD | 0 | A | 11.25 | 1255HWa0811467921 | NEW | yes | yes | REI 60-A1 - D,s2-d0 +A1 | 0 | no | 0 | no | Codetext
 | H2 Ebene +3 | WA-DL | 1255Wa 0811467925 | yes | Codetext | m³ | Zimmer- und Holzbauarbeiten | Wand | Außenwand 7-Schalig | WA-DL | 0 | A | 11.25 | 1255HWa0811467921 | NEW | no | yes | REI 60-A1 - D,s2-d0 +A1 | 0 | no | 0 | no | Codetext
 | H2 Ebene +3 | WA-LB | 1255Wa 0811467926 | yes | Codetext | m² | Trockenbauarbeiten | Wand | Außenwand 7-Schalig | WA-LB | 0 | A | 11.25 | 1255HWa0000001262 | NEW | no | yes | 0 | 0 | no | 0 | no | Codetext
 | H2 Ebene +3 | WA-KL | 1255Wa 0811467927 | yes | Codetext | m² | Zimmer- und Holzbauarbeiten | Wand | Außenwand 7-Schalig | WA-KL | 0 | A | 11.25 | 1255HWa0811467921 | NEW | no | yes | REI 60-A1 - D,s2-d0 +A1 | 0 | no | 0 | no | Codetext
 | H2 Ebene +3 | WA-TL | 1255Wa 0811467928 | yes | Codetext | m² | Zimmer- und Holzbauarbeiten | Wand | Außenwand 7-Schalig | WA-TL | 0 | A | 11.25 | 1255HWa0811467921 | NEW | no | yes | REI 60-A1 - D,s2-d0 +A1 | 0 | no | 0 | no | Codetext
 | H2 Ebene +3 | WA-HS | 1255Wa 0811467929 | yes | Codetext | m² | Zimmer- und Holzbauarbeiten | Wand | Außenwand 7-Schalig | WA-HS | 0 | A | 11.25 | 1255HWa0811467921 | NEW | no | yes | REI 60-A1 - D,s2-d0 +A1 | 0 | no | 0 | no | Codetext
2x Gipsfaserplatte | H2 Ebene +3 | WA-LB | 1255Wa 0000001291 | yes |  | m² | Trockenbauarbeiten | Wand | 2x Gipsfaserplatte | WA-LB |  |  | 11.25 | 1255HWa0000001262 | NEW | no | yes | REI 60-A1 - D,s2-d0 +A1
Holzständer + Zwischendämmung | H2 Ebene +3 | WA-HD | 1255Wa 0000001345 | yes |  | m³ | Zimmer- und Holzbauarbeiten | Wand | Holzständer + Zwischendämmung | WA-HD |  |  | 11.25 | 1255HWa0000001262 | NEW | no | yes | REI 60-A1 - D,s2-d0 +A1 | AllplanAttributes - ash D_Detailverweis: DT D; ash D_Plannummer: D1851
Staffel + Zwischendämmung | H2 Ebene +3 | WA-DL | 1255Wa 0000001335 | yes |  | m³ | Zimmer- und Holzbauarbeiten | Wand | Staffel + Zwischendämmung | WA-DL |  |  | 11.25 | 1255HWa0000001262 | NEW | no | yes | REI 60-A1 - D,s2-d0 +A1
 | H2 Ebene +3 | WA-LB | 1255Wa 0000001324 | yes | Codetext | m² | Trockenbauarbeiten | Wand | Außenwand 7-Schalig | WA-LB | 0 | A | 11.25 | 1255HWa0000001262 | NEW | no | yes | 0 | 0 | no | 0 | no | Codetext
Konterlattung | H2 Ebene +3 | WA-KL | 1255Wa 0000001313 | yes |  | m² | Zimmer- und Holzbauarbeiten | Wand | Konterlattung | WA-KL |  |  | 11.25 | 1255HWa0000001262 | NEW | no | yes | REI 60-A1 - D,s2-d0 +A1
Traglattung | H2 Ebene +3 | WA-TL | 1255Wa 0000001302 | yes |  | m² | Zimmer- und Holzbauarbeiten | Wand | Traglattung | WA-TL |  |  | 11.25 | 1255HWa0000001262 | NEW | no | yes | REI 60-A1 - D,s2-d0 +A1
Holzschindel | H2 Ebene +3 | WA-HS | 1255Wa 0000001355 | yes |  | m² | Zimmer- und Holzbauarbeiten | Wand | Holzschindel | WA-HS |  |  | 11.25 | 1255HWa0000001262 | NEW | no | yes | REI 60-A1 - D,s2-d0 +A1
 | H2 Ebene +3 | WA-LB | 1255Wa 0811420052 | yes |  | m² | Trockenbauarbeiten | Wand | Außenwand 7-Schalig | WA-LB |  |  | 11.25 | 1255HWa0811420051 | NEW |  | yes | REI 60-A1 - D,s2-d0 +A1
 | H2 Ebene +3 | WA-HD | 1255Wa 0811420053 | yes |  | m³ | Zimmer- und Holzbauarbeiten | Wand | Außenwand 7-Schalig | WA-HD |  |  | 11.25 | 1255HWa0811420051 | NEW |  | yes | REI 60-A1 - D,s2-d0 +A1 | AllplanAttributes - ash D_Detailverweis: DT D; ash D_Plannummer: D1851
 | H2 Ebene +3 | WA-DL | 1255Wa 0811420054 | yes |  | m³ | Zimmer- und Holzbauarbeiten | Wand | Außenwand 7-Schalig | WA-DL |  |  | 11.25 | 1255HWa0811420051 | NEW |  | yes | REI 60-A1 - D,s2-d0 +A1
 | H2 Ebene +3 | WA-LB | 1255Wa 0811420055 | yes | Codetext | m² | Trockenbauarbeiten | Wand | Außenwand 7-Schalig | WA-LB | 0 | A | 11.25 | 1255HWa0811420051 | NEW |  | yes | 0 | 0 | no | 0 | no | Codetext
 | H2 Ebene +3 | WA-KL | 1255Wa 0811420056 | yes |  | m² | Zimmer- und Holzbauarbeiten | Wand | Außenwand 7-Schalig | WA-KL |  |  | 11.25 | 1255HWa0811420051 | NEW |  | yes | REI 60-A1 - D,s2-d0 +A1
 | H2 Ebene +3 | WA-TL | 1255Wa 0811420057 | yes |  | m² | Zimmer- und Holzbauarbeiten | Wand | Außenwand 7-Schalig | WA-TL |  |  | 11.25 | 1255HWa0811420051 | NEW |  | yes | REI 60-A1 - D,s2-d0 +A1
 | H2 Ebene +3 | WA-LB | 1255Wa 0000001415 | yes | Codetext | m² | Trockenbauarbeiten | Wand | Außenwand 7-Schalig | WA-LB | 0 | A | 11.25 | 1255HWa0000000069 | NEW | no | yes | 0 | 0 | no | 0 | no | Codetext
 | H2 Ebene +3 | WA-DL | 1255Wa 0000001371 | yes | Codetext | m³ | Zimmer- und Holzbauarbeiten | Wand | Außenwand 7-Schalig | WA-DL | 0 | A | 11.25 | 1255HWa0000000069 | NEW | no | yes | 0 | 0 | no | 0 | no | Codetext | AllplanAttributes - ash D_Detailverweis: DT D; ash D_Plannummer: D1851
 | H2 Ebene +3 | WA-DL | 1255Wa 0000001361 | yes | Codetext | m³ | Zimmer- und Holzbauarbeiten | Wand | Außenwand 7-Schalig | WA-DL | 0 | A | 11.25 | 1255HWa0000000069 | NEW | no | yes | 0 | 0 | no | 0 | no | Codetext
 | H2 Ebene +3 | WA-LB | 1255Wa 0000001365 | yes | Codetext | m² | Trockenbauarbeiten | Wand | Außenwand 7-Schalig | WA-LB | 0 | A | 11.25 | 1255HWa0000000069 | NEW | no | yes | 0 | 0 | no | 0 | no | Codetext
 | H2 Ebene +3 | WA-KL | 1255Wa 0000001363 | yes | Codetext | m² | Zimmer- und Holzbauarbeiten | Wand | Außenwand 7-Schalig | WA-KL | 0 | A | 11.25 | 1255HWa0000000069 | NEW | no | yes | 0 | 0 | no | 0 | no | Codetext
 | H2 Ebene +3 | WA-TL | 1255Wa 0000001357 | yes | Codetext | m² | Zimmer- und Holzbauarbeiten | Wand | Außenwand 7-Schalig | WA-TL | 0 | A | 11.25 | 1255HWa0000000069 | NEW | no | yes | 0 | 0 | no | 0 | no | Codetext
 | H2 Ebene +3 | WA-HS | 1255Wa 0000001359 | yes | Codetext | m² | Zimmer- und Holzbauarbeiten | Wand | Außenwand 7-Schalig | WA-HS | 0 | A | 11.25 | 1255HWa0000000069 | NEW | no | yes | 0 | 0 | no | 0 | no | Codetext
2x Gipsfaserplatte | H2 Ebene +3 | WA-LB | 1255Wa 0000007777 | yes |  | m² | Trockenbauarbeiten | Wand | 2x Gipsfaserplatte | WA-LB |  |  | 11.25 | 1255HWa0000007776 | NEW | no | yes | REI 60-A1 - D,s2-d0 +A1
Holzständer + Zwischendämmung | H2 Ebene +3 | WA-HD | 1255Wa 0000007778 | yes |  | m³ | Zimmer- und Holzbauarbeiten | Wand | Holzständer + Zwischendämmung | WA-HD |  |  | 11.25 | 1255HWa0000007776 | NEW | no | yes | REI 60-A1 - D,s2-d0 +A1 | AllplanAttributes - ash D_Detailverweis: DT D; ash D_Plannummer: D1851
Staffel + Zwischendämmung | H2 Ebene +3 | WA-DL | 1255Wa 0000007779 | yes |  | m³ | Zimmer- und Holzbauarbeiten | Wand | Staffel + Zwischendämmung | WA-DL |  |  | 11.25 | 1255HWa0000007776 | NEW | no | yes | REI 60-A1 - D,s2-d0 +A1
 | H2 Ebene +3 | WA-LB | 1255Wa 0000007780 | yes | Codetext | m² | Trockenbauarbeiten | Wand | Außenwand 7-Schalig | WA-LB | 0 | A | 11.25 | 1255HWa0000007776 | NEW | no | yes | 0 | 0 | no | 0 | no | Codetext
Konterlattung | H2 Ebene +3 | WA-KL | 1255Wa 0000007781 | yes |  | m² | Zimmer- und Holzbauarbeiten | Wand | Konterlattung | WA-KL |  |  | 11.25 | 1255HWa0000007776 | NEW | no | yes | REI 60-A1 - D,s2-d0 +A1
Traglattung | H2 Ebene +3 | WA-TL | 1255Wa 0000007782 | yes |  | m² | Zimmer- und Holzbauarbeiten | Wand | Traglattung | WA-TL |  |  | 11.25 | 1255HWa0000007776 | NEW | no | yes | REI 60-A1 - D,s2-d0 +A1
Holzschindel | H2 Ebene +3 | WA-HS | 1255Wa 0000007783 | yes |  | m² | Zimmer- und Holzbauarbeiten | Wand | Holzschindel | WA-HS |  |  | 11.25 | 1255HWa0000007776 | NEW | no | yes | REI 60-A1 - D,s2-d0 +A1
 | H2 Ebene +3 | WA-LB | 1255Wa 0000000759 | yes | Codetext | m² | Trockenbauarbeiten | Wand | Außenwand 7-Schalig | WA-LB | 0 | A | 11.25 | 1255HWa0000000072 | NEW | no | yes | 0 | 0 | no | 0 | no | Codetext
 | H2 Ebene +3 | WA-DL | 1255Wa 0000000755 | yes | Codetext | m³ | Zimmer- und Holzbauarbeiten | Wand | Außenwand 7-Schalig | WA-DL | 0 | A | 11.25 | 1255HWa0000000072 | NEW | no | yes | 0 | 0 | no | 0 | no | Codetext | AllplanAttributes - ash D_Detailverweis: DT D; ash D_Plannummer: D1851
 | H2 Ebene +3 | WA-DL | 1255Wa 0000001391 | yes | Codetext | m³ | Zimmer- und Holzbauarbeiten | Wand | Außenwand 7-Schalig | WA-DL | 0 | A | 11.25 | 1255HWa0000000072 | NEW | no | yes | 0 | 0 | no | 0 | no | Codetext
 | H2 Ebene +3 | WA-LB | 1255Wa 0000001387 | yes | Codetext | m² | Trockenbauarbeiten | Wand | Außenwand 7-Schalig | WA-LB | 0 | A | 11.25 | 1255HWa0000000072 | NEW | no | yes | 0 | 0 | no | 0 | no | Codetext
 | H2 Ebene +3 | WA-KL | 1255Wa 0000001383 | yes | Codetext | m² | Zimmer- und Holzbauarbeiten | Wand | Außenwand 7-Schalig | WA-KL | 0 | A | 11.25 | 1255HWa0000000072 | NEW | no | yes | 0 | 0 | no | 0 | no | Codetext
 | H2 Ebene +3 | WA-TL | 1255Wa 0000001379 | yes | Codetext | m² | Zimmer- und Holzbauarbeiten | Wand | Außenwand 7-Schalig | WA-TL | 0 | A | 11.25 | 1255HWa0000000072 | NEW | no | yes | 0 | 0 | no | 0 | no | Codetext
 | H2 Ebene +3 | WA-HS | 1255Wa 0000001375 | yes | Codetext | m² | Zimmer- und Holzbauarbeiten | Wand | Außenwand 7-Schalig | WA-HS | 0 | A | 11.25 | 1255HWa0000000072 | NEW | no | yes | 0 | 0 | no | 0 | no | Codetext
 | H2 Ebene +3 | WA-LB | 1255Wa 0811427579 | yes | Codetext | m² | Trockenbauarbeiten | Wand | Außenwand 7-Schalig | WA-LB | 0 | A | 11.25 | 1255HWa0811427536 | NEW | no | yes | 0 | 0 | no | 0 | no | Codetext
 | H2 Ebene +3 | WA-DL | 1255Wa 0811427576 | yes | Codetext | m³ | Zimmer- und Holzbauarbeiten | Wand | Außenwand 7-Schalig | WA-DL | 0 | A | 11.25 | 1255HWa0811427536 | NEW | no | yes | 0 | 0 | no | 0 | no | Codetext | AllplanAttributes - ash D_Detailverweis: DT D; ash D_Plannummer: D1851
 | H2 Ebene +3 | WA-DL | 1255Wa 0811427573 | yes | Codetext | m³ | Zimmer- und Holzbauarbeiten | Wand | Außenwand 7-Schalig | WA-DL | 0 | A | 11.25 | 1255HWa0811427536 | NEW | no | yes | 0 | 0 | no | 0 | no | Codetext
 | H2 Ebene +3 | WA-LB | 1255Wa 0811427570 | yes | Codetext | m² | Trockenbauarbeiten | Wand | Außenwand 7-Schalig | WA-LB | 0 | A | 11.25 | 1255HWa0811427536 | NEW | no | yes | 0 | 0 | no | 0 | no | Codetext
 | H2 Ebene +3 | WA-KL | 1255Wa 0811427567 | yes | Codetext | m² | Zimmer- und Holzbauarbeiten | Wand | Außenwand 7-Schalig | WA-KL | 0 | A | 11.25 | 1255HWa0811427536 | NEW | no | yes | 0 | 0 | no | 0 | no | Codetext
 | H2 Ebene +3 | WA-TL | 1255Wa 0811427564 | yes | Codetext | m² | Zimmer- und Holzbauarbeiten | Wand | Außenwand 7-Schalig | WA-TL | 0 | A | 11.25 | 1255HWa0811427536 | NEW | no | yes | 0 | 0 | no | 0 | no | Codetext
 | H2 Ebene +3 | WA-HS | 1255Wa 0811427561 | yes | Codetext | m² | Zimmer- und Holzbauarbeiten | Wand | Außenwand 7-Schalig | WA-HS | 0 | A | 11.25 | 1255HWa0811427536 | NEW | no | yes | 0 | 0 | no | 0 | no | Codetext
 | H2 Ebene +3 | WA-LB | 1255Wa 0811427606 | yes | Codetext | m² | Trockenbauarbeiten | Wand | Außenwand 7-Schalig | WA-LB | 0 | A | 11.25 | 1255HWa0811427542 | NEW | no | yes | 0 | 0 | no | 0 | no | Codetext
 | H2 Ebene +3 | WA-DL | 1255Wa 0811427608 | yes | Codetext | m³ | Zimmer- und Holzbauarbeiten | Wand | Außenwand 7-Schalig | WA-DL | 0 | A | 11.25 | 1255HWa0811427542 | NEW | no | yes | 0 | 0 | no | 0 | no | Codetext
 | H2 Ebene +3 | WA-DL | 1255Wa 0811427610 | yes | Codetext | m³ | Zimmer- und Holzbauarbeiten | Wand | Außenwand 7-Schalig | WA-DL | 0 | A | 11.25 | 1255HWa0811427542 | NEW | no | yes | 0 | 0 | no | 0 | no | Codetext
 | H2 Ebene +3 | WA-LB | 1255Wa 0811427612 | yes | Codetext | m² | Trockenbauarbeiten | Wand | Außenwand 7-Schalig | WA-LB | 0 | A | 11.25 | 1255HWa0811427542 | NEW | no | yes | 0 | 0 | no | 0 | no | Codetext
 | H2 Ebene +3 | WA-KL | 1255Wa 0811427614 | yes | Codetext | m² | Zimmer- und Holzbauarbeiten | Wand | Außenwand 7-Schalig | WA-KL | 0 | A | 11.25 | 1255HWa0811427542 | NEW | no | yes | 0 | 0 | no | 0 | no | Codetext
 | H2 Ebene +3 | WA-TL | 1255Wa 0811427616 | yes | Codetext | m² | Zimmer- und Holzbauarbeiten | Wand | Außenwand 7-Schalig | WA-TL | 0 | A | 11.25 | 1255HWa0811427542 | NEW | no | yes | 0 | 0 | no | 0 | no | Codetext
 | H2 Ebene +3 | WA-HS | 1255Wa 0811427618 | yes | Codetext | m² | Zimmer- und Holzbauarbeiten | Wand | Außenwand 7-Schalig | WA-HS | 0 | A | 11.25 | 1255HWa0811427542 | NEW | no | yes | 0 | 0 | no | 0 | no | Codetext
 | H2 Ebene +3 | WA-LB | 1255Wa 0811427604 | yes | Codetext | m² | Trockenbauarbeiten | Wand | Außenwand 7-Schalig | WA-LB | 0 | A | 11.25 | 1255HWa0811427588 | NEW | no | yes | 0 | 0 | no | 0 | no | Codetext
 | H2 Ebene +3 | WA-DL | 1255Wa 0811427602 | yes | Codetext | m³ | Zimmer- und Holzbauarbeiten | Wand | Außenwand 7-Schalig | WA-DL | 0 | A | 11.25 | 1255HWa0811427588 | NEW | no | yes | 0 | 0 | no | 0 | no | Codetext
 | H2 Ebene +3 | WA-DL | 1255Wa 0811427600 | yes | Codetext | m³ | Zimmer- und Holzbauarbeiten | Wand | Außenwand 7-Schalig | WA-DL | 0 | A | 11.25 | 1255HWa0811427588 | NEW | no | yes | 0 | 0 | no | 0 | no | Codetext
 | H2 Ebene +3 | WA-LB | 1255Wa 0811427598 | yes | Codetext | m² | Trockenbauarbeiten | Wand | Außenwand 7-Schalig | WA-LB | 0 | A | 11.25 | 1255HWa0811427588 | NEW | no | yes | 0 | 0 | no | 0 | no | Codetext
 | H2 Ebene +3 | WA-KL | 1255Wa 0811427596 | yes | Codetext | m² | Zimmer- und Holzbauarbeiten | Wand | Außenwand 7-Schalig | WA-KL | 0 | A | 11.25 | 1255HWa0811427588 | NEW | no | yes | 0 | 0 | no | 0 | no | Codetext
 | H2 Ebene +3 | WA-TL | 1255Wa 0811427594 | yes | Codetext | m² | Zimmer- und Holzbauarbeiten | Wand | Außenwand 7-Schalig | WA-TL | 0 | A | 11.25 | 1255HWa0811427588 | NEW | no | yes | 0 | 0 | no | 0 | no | Codetext
 | H2 Ebene +3 | WA-HS | 1255Wa 0811427592 | yes | Codetext | m² | Zimmer- und Holzbauarbeiten | Wand | Außenwand 7-Schalig | WA-HS | 0 | A | 11.25 | 1255HWa0811427588 | NEW | no | yes | 0 | 0 | no | 0 | no | Codetext
 | H2 Ebene +3 | WA-LB | 1255Wa 0811437202 | yes | Codetext | m² | Trockenbauarbeiten | Wand | Außenwand 7-Schalig | WA-LB | 0 | A | 11.25 | 1255HWa0811437201 | NEW | no | yes | 0 | 0 | no | 0 | no | Codetext
 | H2 Ebene +3 | WA-DL | 1255Wa 0811437203 | yes | Codetext | m³ | Zimmer- und Holzbauarbeiten | Wand | Außenwand 7-Schalig | WA-DL | 0 | A | 11.25 | 1255HWa0811437201 | NEW | no | yes | 0 | 0 | no | 0 | no | Codetext
 | H2 Ebene +3 | WA-DL | 1255Wa 0811437204 | yes | Codetext | m³ | Zimmer- und Holzbauarbeiten | Wand | Außenwand 7-Schalig | WA-DL | 0 | A | 11.25 | 1255HWa0811437201 | NEW | no | yes | 0 | 0 | no | 0 | no | Codetext
 | H2 Ebene +3 | WA-LB | 1255Wa 0811437205 | yes | Codetext | m² | Trockenbauarbeiten | Wand | Außenwand 7-Schalig | WA-LB | 0 | A | 11.25 | 1255HWa0811437201 | NEW | no | yes | 0 | 0 | no | 0 | no | Codetext
 | H2 Ebene +3 | WA-KL | 1255Wa 0811437206 | yes | Codetext | m² | Zimmer- und Holzbauarbeiten | Wand | Außenwand 7-Schalig | WA-KL | 0 | A | 11.25 | 1255HWa0811437201 | NEW | no | yes | 0 | 0 | no | 0 | no | Codetext
 | H2 Ebene +3 | WA-TL | 1255Wa 0811437207 | yes | Codetext | m² | Zimmer- und Holzbauarbeiten | Wand | Außenwand 7-Schalig | WA-TL | 0 | A | 11.25 | 1255HWa0811437201 | NEW | no | yes | 0 | 0 | no | 0 | no | Codetext
 | H2 Ebene +3 | WA-HS | 1255Wa 0811437208 | yes | Codetext | m² | Zimmer- und Holzbauarbeiten | Wand | Außenwand 7-Schalig | WA-HS | 0 | A | 11.25 | 1255HWa0811437201 | NEW | no | yes | 0 | 0 | no | 0 | no | Codetext
 | H2 Ebene +3 | WA-LB | 1255Wa 0811427707 | yes | Codetext | m² | Trockenbauarbeiten | Wand | Außenwand 7-Schalig | WA-LB | 0 | A | 11.25 | 1255HWa0811427520 | NEW | no | yes | 0 | 0 | no | 0 | no | Codetext
 | H2 Ebene +3 | WA-DL | 1255Wa 0811427705 | yes | Codetext | m³ | Zimmer- und Holzbauarbeiten | Wand | Außenwand 7-Schalig | WA-DL | 0 | A | 11.25 | 1255HWa0811427520 | NEW | no | yes | 0 | 0 | no | 0 | no | Codetext
 | H2 Ebene +3 | WA-DL | 1255Wa 0811427703 | yes | Codetext | m³ | Zimmer- und Holzbauarbeiten | Wand | Außenwand 7-Schalig | WA-DL | 0 | A | 11.25 | 1255HWa0811427520 | NEW | no | yes | 0 | 0 | no | 0 | no | Codetext
 | H2 Ebene +3 | WA-LB | 1255Wa 0811427701 | yes | Codetext | m² | Trockenbauarbeiten | Wand | Außenwand 7-Schalig | WA-LB | 0 | A | 11.25 | 1255HWa0811427520 | NEW | no | yes | 0 | 0 | no | 0 | no | Codetext
 | H2 Ebene +3 | WA-KL | 1255Wa 0811427699 | yes | Codetext | m² | Zimmer- und Holzbauarbeiten | Wand | Außenwand 7-Schalig | WA-KL | 0 | A | 11.25 | 1255HWa0811427520 | NEW | no | yes | 0 | 0 | no | 0 | no | Codetext
 | H2 Ebene +3 | WA-TL | 1255Wa 0811427697 | yes | Codetext | m² | Zimmer- und Holzbauarbeiten | Wand | Außenwand 7-Schalig | WA-TL | 0 | A | 11.25 | 1255HWa0811427520 | NEW | no | yes | 0 | 0 | no | 0 | no | Codetext
 | H2 Ebene +3 | WA-HS | 1255Wa 0811427695 | yes | Codetext | m² | Zimmer- und Holzbauarbeiten | Wand | Außenwand 7-Schalig | WA-HS | 0 | A | 11.25 | 1255HWa0811427520 | NEW | no | yes | 0 | 0 | no | 0 | no | Codetext
 | H2 Ebene +3 | WA-LB | 1255Wa 0811427693 | yes | Codetext | m² | Trockenbauarbeiten | Wand | Außenwand 7-Schalig | WA-LB | 0 | A | 11.25 | 1255HWa0811427521 | NEW | no | yes | 0 | 0 | no | 0 | no | Codetext
 | H2 Ebene +3 | WA-DL | 1255Wa 0811427691 | yes | Codetext | m³ | Zimmer- und Holzbauarbeiten | Wand | Außenwand 7-Schalig | WA-DL | 0 | A | 11.25 | 1255HWa0811427521 | NEW | no | yes | 0 | 0 | no | 0 | no | Codetext
 | H2 Ebene +3 | WA-DL | 1255Wa 0811427689 | yes | Codetext | m³ | Zimmer- und Holzbauarbeiten | Wand | Außenwand 7-Schalig | WA-DL | 0 | A | 11.25 | 1255HWa0811427521 | NEW | no | yes | 0 | 0 | no | 0 | no | Codetext
 | H2 Ebene +3 | WA-LB | 1255Wa 0811427687 | yes | Codetext | m² | Trockenbauarbeiten | Wand | Außenwand 7-Schalig | WA-LB | 0 | A | 11.25 | 1255HWa0811427521 | NEW | no | yes | 0 | 0 | no | 0 | no | Codetext
 | H2 Ebene +3 | WA-KL | 1255Wa 0811427685 | yes | Codetext | m² | Zimmer- und Holzbauarbeiten | Wand | Außenwand 7-Schalig | WA-KL | 0 | A | 11.25 | 1255HWa0811427521 | NEW | no | yes | 0 | 0 | no | 0 | no | Codetext
 | H2 Ebene +3 | WA-TL | 1255Wa 0811427683 | yes | Codetext | m² | Zimmer- und Holzbauarbeiten | Wand | Außenwand 7-Schalig | WA-TL | 0 | A | 11.25 | 1255HWa0811427521 | NEW | no | yes | 0 | 0 | no | 0 | no | Codetext
 | H2 Ebene +3 | WA-HS | 1255Wa 0811427681 | yes | Codetext | m² | Zimmer- und Holzbauarbeiten | Wand | Außenwand 7-Schalig | WA-HS | 0 | A | 11.25 | 1255HWa0811427521 | NEW | no | yes | 0 | 0 | no | 0 | no | Codetext
 | H2 Ebene +3 | WA-LB | 1255Wa 0811437248 | yes | Codetext | m² | Trockenbauarbeiten | Wand | Außenwand 7-Schalig | WA-LB | 0 | A | 11.25 | 1255HWa0811437247 | NEW | no | yes | 0 | 0 | no | 0 | no | Codetext
 | H2 Ebene +3 | WA-DL | 1255Wa 0811437249 | yes | Codetext | m³ | Zimmer- und Holzbauarbeiten | Wand | Außenwand 7-Schalig | WA-DL | 0 | A | 11.25 | 1255HWa0811437247 | NEW | no | yes | 0 | 0 | no | 0 | no | Codetext
 | H2 Ebene +3 | WA-DL | 1255Wa 0811437250 | yes | Codetext | m³ | Zimmer- und Holzbauarbeiten | Wand | Außenwand 7-Schalig | WA-DL | 0 | A | 11.25 | 1255HWa0811437247 | NEW | no | yes | 0 | 0 | no | 0 | no | Codetext
 | H2 Ebene +3 | WA-LB | 1255Wa 0811437251 | yes | Codetext | m² | Trockenbauarbeiten | Wand | Außenwand 7-Schalig | WA-LB | 0 | A | 11.25 | 1255HWa0811437247 | NEW | no | yes | 0 | 0 | no | 0 | no | Codetext
 | H2 Ebene +3 | WA-KL | 1255Wa 0811437252 | yes | Codetext | m² | Zimmer- und Holzbauarbeiten | Wand | Außenwand 7-Schalig | WA-KL | 0 | A | 11.25 | 1255HWa0811437247 | NEW | no | yes | 0 | 0 | no | 0 | no | Codetext
 | H2 Ebene +3 | WA-TL | 1255Wa 0811437253 | yes | Codetext | m² | Zimmer- und Holzbauarbeiten | Wand | Außenwand 7-Schalig | WA-TL | 0 | A | 11.25 | 1255HWa0811437247 | NEW | no | yes | 0 | 0 | no | 0 | no | Codetext
 | H2 Ebene +3 | WA-HS | 1255Wa 0811437254 | yes | Codetext | m² | Zimmer- und Holzbauarbeiten | Wand | Außenwand 7-Schalig | WA-HS | 0 | A | 11.25 | 1255HWa0811437247 | NEW | no | yes | 0 | 0 | no | 0 | no | Codetext
 | H2 Ebene +3 | WA-LB | 1255Wa 0811427766 | yes | Codetext | m² | Trockenbauarbeiten | Wand | Außenwand 7-Schalig | WA-LB | 0 | A | 11.25 | 1255HWa0811427518 | NEW | no | yes | 0 | 0 | no | 0 | no | Codetext
 | H2 Ebene +3 | WA-DL | 1255Wa 0811427761 | yes | Codetext | m³ | Zimmer- und Holzbauarbeiten | Wand | Außenwand 7-Schalig | WA-DL | 0 | A | 11.25 | 1255HWa0811427518 | NEW | no | yes | 0 | 0 | no | 0 | no | Codetext
 | H2 Ebene +3 | WA-DL | 1255Wa 0811427756 | yes | Codetext | m³ | Zimmer- und Holzbauarbeiten | Wand | Außenwand 7-Schalig | WA-DL | 0 | A | 11.25 | 1255HWa0811427518 | NEW | no | yes | 0 | 0 | no | 0 | no | Codetext
 | H2 Ebene +3 | WA-LB | 1255Wa 0811427751 | yes | Codetext | m² | Trockenbauarbeiten | Wand | Außenwand 7-Schalig | WA-LB | 0 | A | 11.25 | 1255HWa0811427518 | NEW | no | yes | 0 | 0 | no | 0 | no | Codetext
 | H2 Ebene +3 | WA-KL | 1255Wa 0811427672 | yes | Codetext | m² | Zimmer- und Holzbauarbeiten | Wand | Außenwand 7-Schalig | WA-KL | 0 | A | 11.25 | 1255HWa0811427518 | NEW | no | yes | 0 | 0 | no | 0 | no | Codetext
 | H2 Ebene +3 | WA-TL | 1255Wa 0811427668 | yes | Codetext | m² | Zimmer- und Holzbauarbeiten | Wand | Außenwand 7-Schalig | WA-TL | 0 | A | 11.25 | 1255HWa0811427518 | NEW | no | yes | 0 | 0 | no | 0 | no | Codetext
 | H2 Ebene +3 | WA-HS | 1255Wa 0811427664 | yes | Codetext | m² | Zimmer- und Holzbauarbeiten | Wand | Außenwand 7-Schalig | WA-HS | 0 | A | 11.25 | 1255HWa0811427518 | NEW | no | yes | 0 | 0 | no | 0 | no | Codetext
 | H2 Ebene +3 | WA-STB | 1255Wa 0811427746 | yes |  | m² | Zimmer- und Holzbauarbeiten | Wand | Außenwand 2-Schalig | WA-STB |  |  | 11.25 | 1255HWa0811427732 | NEW | no |  | 0 | AllplanAttributes - ash D_Detailverweis: DT 3; ash D_Plannummer: D1615
 | H2 Ebene +3 | WA-DL | 1255Wa 0811427744 | yes |  | m³ | Zimmer- und Holzbauarbeiten | Wand | Außenwand 2-Schalig | WA-DL |  |  | 11.25 | 1255HWa0811427732 | NEW | no |  | 0
 | H2 Ebene +3 | WA-LB | 1255Wa 0811427742 | yes | Codetext | m² | Trockenbauarbeiten | Wand | Außenwand 2-Schalig | WA-LB | 0 | A | 11.25 | 1255HWa0811427732 | NEW | no | yes | 0 | 0 | no | 0 | no | Codetext
 | H2 Ebene +3 | WA-TL | 1255Wa 0811427740 | yes |  | m² | Zimmer- und Holzbauarbeiten | Wand | Außenwand 2-Schalig | WA-TL |  |  | 11.25 | 1255HWa0811427732 | NEW | no |  | 0
 | H2 Ebene +3 | WA-TL | 1255Wa 0811427738 | yes |  | m² | Zimmer- und Holzbauarbeiten | Wand | Außenwand 2-Schalig | WA-TL |  |  | 11.25 | 1255HWa0811427732 | NEW | no | yes | REI 60-A1 - D,s2-d0 +A1
 | H2 Ebene +3 | WA-HS | 1255Wa 0811427736 | yes |  | m² | Zimmer- und Holzbauarbeiten | Wand | Außenwand 2-Schalig | WA-HS |  |  | 11.25 | 1255HWa0811427732 | NEW | no |  | 0
 | H2 Ebene +3 | WA-STB | 1255Wa 0811427844 | yes | Codetext | m² | Zimmer- und Holzbauarbeiten | Wand | Außenwand 2-Schalig | WA-STB | 0 | A | 11.25 | 1255HWa0811427522 | NEW | no | yes | 0 | 0 | no | 0 | no | Codetext
 | H2 Ebene +3 | WA-DL | 1255Wa 0811427834 | yes | Codetext | m³ | Zimmer- und Holzbauarbeiten | Wand | Außenwand 2-Schalig | WA-DL | 0 | A | 11.25 | 1255HWa0811427522 | NEW | no | yes | 0 | 0 | no | 0 | no | Codetext
 | H2 Ebene +3 | WA-LB | 1255Wa 0811427836 | yes | Codetext | m² | Trockenbauarbeiten | Wand | Außenwand 2-Schalig | WA-LB | 0 | A | 11.25 | 1255HWa0811427522 | NEW | no | yes | 0 | 0 | no | 0 | no | Codetext
 | H2 Ebene +3 | WA-KL | 1255Wa 0811427838 | yes | Codetext | m² | Zimmer- und Holzbauarbeiten | Wand | Außenwand 2-Schalig | WA-KL | 0 | A | 11.25 | 1255HWa0811427522 | NEW | no | yes | 0 | 0 | no | 0 | no | Codetext
 | H2 Ebene +3 | WA-TL | 1255Wa 0811427840 | yes | Codetext | m² | Zimmer- und Holzbauarbeiten | Wand | Außenwand 2-Schalig | WA-TL | 0 | A | 11.25 | 1255HWa0811427522 | NEW | no | yes | 0 | 0 | no | 0 | no | Codetext
 | H2 Ebene +3 | WA-HS | 1255Wa 0811427842 | yes | Codetext | m² | Zimmer- und Holzbauarbeiten | Wand | Außenwand 2-Schalig | WA-HS | 0 | A | 11.25 | 1255HWa0811427522 | NEW | no | yes | 0 | 0 | no | 0 | no | Codetext
 | H2 Ebene +3 | WA-LB | 1255Wa 0811453719 | yes | Codetext | m² | Trockenbauarbeiten | Wand | Außenwand 7-Schalig | WA-LB | 0 | A | 11.25 | 1255HWa0811453711 | NEW | no | yes | 0 | 0 | no | 0 | no | Codetext
 | H2 Ebene +3 | WA-DL | 1255Wa 0811453718 | yes | Codetext | m³ | Zimmer- und Holzbauarbeiten | Wand | Außenwand 7-Schalig | WA-DL | 0 | A | 11.25 | 1255HWa0811453711 | NEW | no | yes | 0 | 0 | no | 0 | no | Codetext
 | H2 Ebene +3 | WA-DL | 1255Wa 0811453717 | yes | Codetext | m³ | Zimmer- und Holzbauarbeiten | Wand | Außenwand 7-Schalig | WA-DL | 0 | A | 11.25 | 1255HWa0811453711 | NEW | no | yes | 0 | 0 | no | 0 | no | Codetext
 | H2 Ebene +3 | WA-LB | 1255Wa 0811453716 | yes | Codetext | m² | Trockenbauarbeiten | Wand | Außenwand 7-Schalig | WA-LB | 0 | A | 11.25 | 1255HWa0811453711 | NEW | no | yes | 0 | 0 | no | 0 | no | Codetext
 | H2 Ebene +3 | WA-KL | 1255Wa 0811453715 | yes | Codetext | m² | Zimmer- und Holzbauarbeiten | Wand | Außenwand 7-Schalig | WA-KL | 0 | A | 11.25 | 1255HWa0811453711 | NEW | no | yes | 0 | 0 | no | 0 | no | Codetext
 | H2 Ebene +3 | WA-TL | 1255Wa 0811453714 | yes | Codetext | m² | Zimmer- und Holzbauarbeiten | Wand | Außenwand 7-Schalig | WA-TL | 0 | A | 11.25 | 1255HWa0811453711 | NEW | no | yes | 0 | 0 | no | 0 | no | Codetext
 | H2 Ebene +3 | WA-HS | 1255Wa 0811453713 | yes | Codetext | m² | Zimmer- und Holzbauarbeiten | Wand | Außenwand 7-Schalig | WA-HS | 0 | A | 11.25 | 1255HWa0811453711 | NEW | no | yes | 0 | 0 | no | 0 | no | Codetext
2x Gipsfaserplatte | H2 Ebene +3 | WA-LB | 1255Wa 0811453593 | yes |  | m² | Trockenbauarbeiten | Wand | 2x Gipsfaserplatte | WA-LB |  |  | 11.25 | 1255HWa0811453583 | NEW | no | yes | REI 60-A1 - D,s2-d0 +A1
2x Gipsfaserplatte | H2 Ebene +3 | WA-LB | 1255Wa 0811453592 | yes |  | m² | Trockenbauarbeiten | Wand | 2x Gipsfaserplatte | WA-LB |  |  | 11.25 | 1255HWa0811453583 | NEW | no | yes | 0 | 0.9 |  | 32 | AllplanAttributes - Sicherheitsklasse: -; Sonnenschutztyp: Movable; g-Wert: 0,51
Holzständer + Zwischendämmung | H2 Ebene +3 | WA-HD | 1255Wa 0811453591 | yes |  | m³ | Zimmer- und Holzbauarbeiten | Wand | Holzständer + Zwischendämmung | WA-HD |  |  | 11.25 | 1255HWa0811453583 | NEW | no | yes | REI 60-A1 - D,s2-d0 +A1 | AllplanAttributes - ash D_Detailverweis: DT A; ash D_Plannummer: D1850
 | H2 Ebene +3 | WA-LB | 1255Wa 0811453590 | yes | Codetext | m² | Trockenbauarbeiten | Wand | Außenwand 7-Schalig | WA-LB | 0 | A | 11.25 | 1255HWa0811453583 | NEW | no | yes | 0 | 0.9 | no | 32 | no | Codetext | AllplanAttributes - Sicherheitsklasse: -; Sonnenschutztyp: Movable; g-Wert: 0,51
 | H2 Ebene +3 | WA-LB | 1255Wa 0811453589 | yes | Codetext | m² | Trockenbauarbeiten | Wand | Außenwand 7-Schalig | WA-LB | 0 | A | 11.25 | 1255HWa0811453583 | NEW | no | yes | 0 | 0 | no | 0 | no | Codetext
Staffel + Zwischendämmung | H2 Ebene +3 | WA-DL | 1255Wa 0811453588 | yes |  | m³ | Zimmer- und Holzbauarbeiten | Wand | Staffel + Zwischendämmung | WA-DL |  |  | 11.25 | 1255HWa0811453583 | NEW | no | yes | REI 60-A1 - D,s2-d0 +A1
Konterlattung | H2 Ebene +3 | WA-KL | 1255Wa 0811453587 | yes |  | m² | Zimmer- und Holzbauarbeiten | Wand | Konterlattung | WA-KL |  |  | 11.25 | 1255HWa0811453583 | NEW | no | yes | REI 60-A1 - D,s2-d0 +A1
Traglattung | H2 Ebene +3 | WA-TL | 1255Wa 0811453586 | yes |  | m² | Zimmer- und Holzbauarbeiten | Wand | Traglattung | WA-TL |  |  | 11.25 | 1255HWa0811453583 | NEW | no | yes | REI 60-A1 - D,s2-d0 +A1
Holzschindel | H2 Ebene +3 | WA-HS | 1255Wa 0811453585 | yes |  | m² | Zimmer- und Holzbauarbeiten | Wand | Holzschindel | WA-HS |  |  | 11.25 | 1255HWa0811453583 | NEW | no | yes | REI 60-A1 - D,s2-d0 +A1 | AllplanAttributes - ash D_Detailverweis: DT 4; ash D_Plannummer: D1615
 | H2 Ebene +3 | WA-LB | 1255Wa 0000001954 | yes | Codetext | m² | Trockenbauarbeiten | Wand | Außenwand 7-Schalig | WA-LB | 0 | A | 11.25 | 1255HWa0000000073 | NEW | no | yes | 0 | 0 | no | 0 | no | Codetext
 | H2 Ebene +3 | WA-DL | 1255Wa 0000001958 | yes | Codetext | m³ | Zimmer- und Holzbauarbeiten | Wand | Außenwand 7-Schalig | WA-DL | 0 | A | 11.25 | 1255HWa0000000073 | NEW | no | yes | 0 | 0 | no | 0 | no | Codetext | AllplanAttributes - ash D_Detailverweis: DT D; ash D_Plannummer: D1851
 | H2 Ebene +3 | WA-DL | 1255Wa 0000001956 | yes | Codetext | m³ | Zimmer- und Holzbauarbeiten | Wand | Außenwand 7-Schalig | WA-DL | 0 | A | 11.25 | 1255HWa0000000073 | NEW | no | yes | 0 | 0 | no | 0 | no | Codetext
 | H2 Ebene +3 | WA-LB | 1255Wa 0000001960 | yes | Codetext | m² | Trockenbauarbeiten | Wand | Außenwand 7-Schalig | WA-LB | 0 | A | 11.25 | 1255HWa0000000073 | NEW | no | yes | 0 | 0 | no | 0 | no | Codetext
 | H2 Ebene +3 | WA-KL | 1255Wa 0000001964 | yes | Codetext | m² | Zimmer- und Holzbauarbeiten | Wand | Außenwand 7-Schalig | WA-KL | 0 | A | 11.25 | 1255HWa0000000073 | NEW | no | yes | 0 | 0 | no | 0 | no | Codetext
 | H2 Ebene +3 | WA-TL | 1255Wa 0000001962 | yes | Codetext | m² | Zimmer- und Holzbauarbeiten | Wand | Außenwand 7-Schalig | WA-TL | 0 | A | 11.25 | 1255HWa0000000073 | NEW | no | yes | 0 | 0 | no | 0 | no | Codetext
 | H2 Ebene +3 | WA-HS | 1255Wa 0000001966 | yes | Codetext | m² | Zimmer- und Holzbauarbeiten | Wand | Außenwand 7-Schalig | WA-HS | 0 | A | 11.25 | 1255HWa0000000073 | NEW | no | yes | 0 | 0 | no | 0 | no | Codetext
2x Gipsfaserplatte | H2 Ebene +3 | WA-LB | 1255Wa 0000001928 | yes |  | m² | Trockenbauarbeiten | Wand | 2x Gipsfaserplatte | WA-LB |  |  | 11.25 | 1255HWa0000001749 | NEW | no | yes | REI 60-A1 - D,s2-d0 +A1
Holzständer + Zwischendämmung | H2 Ebene +3 | WA-HD | 1255Wa 0000001922 | yes |  | m³ | Zimmer- und Holzbauarbeiten | Wand | Holzständer + Zwischendämmung | WA-HD |  |  | 11.25 | 1255HWa0000001749 | NEW | no | yes | REI 60-A1 - D,s2-d0 +A1 | AllplanAttributes - ash D_Detailverweis: DT D; ash D_Plannummer: D1851
Staffel + Zwischendämmung | H2 Ebene +3 | WA-DL | 1255Wa 0000001917 | yes |  | m³ | Zimmer- und Holzbauarbeiten | Wand | Staffel + Zwischendämmung | WA-DL |  |  | 11.25 | 1255HWa0000001749 | NEW | no | yes | REI 60-A1 - D,s2-d0 +A1
 | H2 Ebene +3 | WA-LB | 1255Wa 0000001912 | yes | Codetext | m² | Trockenbauarbeiten | Wand | Außenwand 7-Schalig | WA-LB | 0 | A | 11.25 | 1255HWa0000001749 | NEW | no | yes | 0 | 0 | no | 0 | no | Codetext
Konterlattung | H2 Ebene +3 | WA-KL | 1255Wa 0000001907 | yes |  | m² | Zimmer- und Holzbauarbeiten | Wand | Konterlattung | WA-KL |  |  | 11.25 | 1255HWa0000001749 | NEW | no | yes | REI 60-A1 - D,s2-d0 +A1
Traglattung | H2 Ebene +3 | WA-TL | 1255Wa 0000001902 | yes |  | m² | Zimmer- und Holzbauarbeiten | Wand | Traglattung | WA-TL |  |  | 11.25 | 1255HWa0000001749 | NEW | no | yes | REI 60-A1 - D,s2-d0 +A1
Holzschindel | H2 Ebene +3 | WA-HS | 1255Wa 0000001897 | yes |  | m² | Zimmer- und Holzbauarbeiten | Wand | Holzschindel | WA-HS |  |  | 11.25 | 1255HWa0000001749 | NEW | no | yes | REI 60-A1 - D,s2-d0 +A1
2x Gipsfaserplatte | H2 Ebene +3 | WA-LB | 1255Wa 0000011665 | yes |  | m² | Trockenbauarbeiten | Wand | 2x Gipsfaserplatte | WA-LB |  |  | 11.25 | 1255HWa0000011635 | NEW | no | yes | REI 60-A1 - D,s2-d0 +A1
Holzständer + Zwischendämmung | H2 Ebene +3 | WA-HD | 1255Wa 0000011664 | yes |  | m³ | Zimmer- und Holzbauarbeiten | Wand | Holzständer + Zwischendämmung | WA-HD |  |  | 11.25 | 1255HWa0000011635 | NEW | no | yes | REI 60-A1 - D,s2-d0 +A1
Staffel + Zwischendämmung | H2 Ebene +3 | WA-DL | 1255Wa 0000011663 | yes |  | m³ | Zimmer- und Holzbauarbeiten | Wand | Staffel + Zwischendämmung | WA-DL |  |  | 11.25 | 1255HWa0000011635 | NEW | no | yes | REI 60-A1 - D,s2-d0 +A1
 | H2 Ebene +3 | WA-LB | 1255Wa 0000011662 | yes | Codetext | m² | Trockenbauarbeiten | Wand | Außenwand 7-Schalig | WA-LB | 0 | A | 11.25 | 1255HWa0000011635 | NEW | no | yes | 0 | 0 | no | 0 | no | Codetext
Konterlattung | H2 Ebene +3 | WA-KL | 1255Wa 0000011661 | yes |  | m² | Zimmer- und Holzbauarbeiten | Wand | Konterlattung | WA-KL |  |  | 11.25 | 1255HWa0000011635 | NEW | no | yes | REI 60-A1 - D,s2-d0 +A1
Traglattung | H2 Ebene +3 | WA-TL | 1255Wa 0000011660 | yes |  | m² | Zimmer- und Holzbauarbeiten | Wand | Traglattung | WA-TL |  |  | 11.25 | 1255HWa0000011635 | NEW | no | yes | REI 60-A1 - D,s2-d0 +A1
Holzschindel | H2 Ebene +3 | WA-HS | 1255Wa 0000011666 | yes |  | m² | Zimmer- und Holzbauarbeiten | Wand | Holzschindel | WA-HS |  |  | 11.25 | 1255HWa0000011635 | NEW | no | yes | REI 60-A1 - D,s2-d0 +A1
 | H2 Ebene +3 | WA-LB | 1255Wa 0000004744 | yes | Codetext | m² | Trockenbauarbeiten | Wand | Außenwand 7-Schalig | WA-LB | 0 | A | 11.25 | 1255HWa0000004492 | NEW | no | yes | 0 | 0 | no | 0 | no | Codetext
 | H2 Ebene +3 | WA-DL | 1255Wa 0000004752 | yes | Codetext | m³ | Zimmer- und Holzbauarbeiten | Wand | Außenwand 7-Schalig | WA-DL | 0 | A | 11.25 | 1255HWa0000004492 | NEW | no | yes | 0 | 0 | no | 0 | no | Codetext
 | H2 Ebene +3 | WA-DL | 1255Wa 0000004760 | yes | Codetext | m³ | Zimmer- und Holzbauarbeiten | Wand | Außenwand 7-Schalig | WA-DL | 0 | A | 11.25 | 1255HWa0000004492 | NEW | no | yes | 0 | 0 | no | 0 | no | Codetext
 | H2 Ebene +3 | WA-LB | 1255Wa 0000004768 | yes | Codetext | m² | Trockenbauarbeiten | Wand | Außenwand 7-Schalig | WA-LB | 0 | A | 11.25 | 1255HWa0000004492 | NEW | no | yes | 0 | 0 | no | 0 | no | Codetext
 | H2 Ebene +3 | WA-KL | 1255Wa 0000004776 | yes | Codetext | m² | Zimmer- und Holzbauarbeiten | Wand | Außenwand 7-Schalig | WA-KL | 0 | A | 11.25 | 1255HWa0000004492 | NEW | no | yes | 0 | 0 | no | 0 | no | Codetext
 | H2 Ebene +3 | WA-TL | 1255Wa 0000004784 | yes | Codetext | m² | Zimmer- und Holzbauarbeiten | Wand | Außenwand 7-Schalig | WA-TL | 0 | A | 11.25 | 1255HWa0000004492 | NEW | no | yes | 0 | 0 | no | 0 | no | Codetext
 | H2 Ebene +3 | WA-HS | 1255Wa 0000004792 | yes | Codetext | m² | Zimmer- und Holzbauarbeiten | Wand | Außenwand 7-Schalig | WA-HS | 0 | A | 11.25 | 1255HWa0000004492 | NEW | no | yes | 0 | 0 | no | 0 | no | Codetext
 | H2 Ebene +3 | WA-LB | 1255Wa 0811466416 | yes | Codetext | m² | Trockenbauarbeiten | Wand | Außenwand 7-Schalig | WA-LB | 0 | A | 11.25 | 1255HWa0811466409 | NEW | no | yes | REI 60-A1 - D,s2-d0 +A1 | 0 | no | 0 | no | Codetext
 | H2 Ebene +3 | WA-HD | 1255Wa 0811466420 | yes | Codetext | m³ | Zimmer- und Holzbauarbeiten | Wand | Außenwand 7-Schalig | WA-HD | 0 | A | 11.25 | 1255HWa0811466409 | NEW | yes | yes | REI 60-A1 - D,s2-d0 +A1 | 0 | no | 0 | no | Codetext
 | H2 Ebene +3 | WA-DL | 1255Wa 0811466424 | yes | Codetext | m³ | Zimmer- und Holzbauarbeiten | Wand | Außenwand 7-Schalig | WA-DL | 0 | A | 11.25 | 1255HWa0811466409 | NEW | no | yes | REI 60-A1 - D,s2-d0 +A1 | 0 | no | 0 | no | Codetext
 | H2 Ebene +3 | WA-LB | 1255Wa 0811466428 | yes | Codetext | m² | Trockenbauarbeiten | Wand | Außenwand 7-Schalig | WA-LB | 0 | A | 11.25 | 1255HWa0811466409 | NEW | no | yes | REI 60-A1 - D,s2-d0 +A1 | 0 | no | 0 | no | Codetext
 | H2 Ebene +3 | WA-KL | 1255Wa 0811466432 | yes | Codetext | m² | Zimmer- und Holzbauarbeiten | Wand | Außenwand 7-Schalig | WA-KL | 0 | A | 11.25 | 1255HWa0811466409 | NEW | no | yes | REI 60-A1 - D,s2-d0 +A1 | 0 | no | 0 | no | Codetext
 | H2 Ebene +3 | WA-TL | 1255Wa 0811466436 | yes | Codetext | m² | Zimmer- und Holzbauarbeiten | Wand | Außenwand 7-Schalig | WA-TL | 0 | A | 11.25 | 1255HWa0811466409 | NEW | no | yes | REI 60-A1 - D,s2-d0 +A1 | 0 | no | 0 | no | Codetext
 | H2 Ebene +3 | WA-HS | 1255Wa 0811466440 | yes | Codetext | m² | Zimmer- und Holzbauarbeiten | Wand | Außenwand 7-Schalig | WA-HS | 0 | A | 11.25 | 1255HWa0811466409 | NEW | no | yes | REI 60-A1 - D,s2-d0 +A1 | 0 | no | 0 | no | Codetext
 | H2 Ebene +3 | WA-LB | 1255Wa 0000002160 | yes | Codetext | m² | Trockenbauarbeiten | Wand | Außenwand 7-Schalig | WA-LB | 0 | A | 11.25 | 1255HWa0000002012 | NEW | no | yes | 0 | 0 | no | 0 | no | Codetext
 | H2 Ebene +3 | WA-DL | 1255Wa 0000002168 | yes | Codetext | m³ | Zimmer- und Holzbauarbeiten | Wand | Außenwand 7-Schalig | WA-DL | 0 | A | 11.25 | 1255HWa0000002012 | NEW | no | yes | 0 | 0 | no | 0 | no | Codetext
 | H2 Ebene +3 | WA-DL | 1255Wa 0000002176 | yes | Codetext | m³ | Zimmer- und Holzbauarbeiten | Wand | Außenwand 7-Schalig | WA-DL | 0 | A | 11.25 | 1255HWa0000002012 | NEW | no | yes | 0 | 0 | no | 0 | no | Codetext
 | H2 Ebene +3 | WA-LB | 1255Wa 0000002184 | yes | Codetext | m² | Trockenbauarbeiten | Wand | Außenwand 7-Schalig | WA-LB | 0 | A | 11.25 | 1255HWa0000002012 | NEW | no | yes | 0 | 0 | no | 0 | no | Codetext
 | H2 Ebene +3 | WA-KL | 1255Wa 0000002192 | yes | Codetext | m² | Zimmer- und Holzbauarbeiten | Wand | Außenwand 7-Schalig | WA-KL | 0 | A | 11.25 | 1255HWa0000002012 | NEW | no | yes | 0 | 0 | no | 0 | no | Codetext
 | H2 Ebene +3 | WA-TL | 1255Wa 0000002200 | yes | Codetext | m² | Zimmer- und Holzbauarbeiten | Wand | Außenwand 7-Schalig | WA-TL | 0 | A | 11.25 | 1255HWa0000002012 | NEW | no | yes | 0 | 0 | no | 0 | no | Codetext
 | H2 Ebene +3 | WA-HS | 1255Wa 0000002208 | yes | Codetext | m² | Zimmer- und Holzbauarbeiten | Wand | Außenwand 7-Schalig | WA-HS | 0 | A | 11.25 | 1255HWa0000002012 | NEW | no | yes | 0 | 0 | no | 0 | no | Codetext
 | H2 Ebene +3 | WA-LB | 1255Wa 0811561858 | yes | Codetext | m² | Trockenbauarbeiten | Wand | Außenwand 7-Schalig | WA-LB | 0 | A | 11.25 | 1255HWa0000000073 | NEW | no | yes | 0 | 0 | no | 0 | no | Codetext
 | H2 Ebene +3 | WA-DL | 1255Wa 0811561859 | yes | Codetext | m³ | Zimmer- und Holzbauarbeiten | Wand | Außenwand 7-Schalig | WA-DL | 0 | A | 11.25 | 1255HWa0000000073 | NEW | no | yes | 0 | 0 | no | 0 | no | Codetext | AllplanAttributes - ash D_Detailverweis: DT D; ash D_Plannummer: D1851
 | H2 Ebene +3 | WA-DL | 1255Wa 0811561860 | yes | Codetext | m³ | Zimmer- und Holzbauarbeiten | Wand | Außenwand 7-Schalig | WA-DL | 0 | A | 11.25 | 1255HWa0000000073 | NEW | no | yes | 0 | 0 | no | 0 | no | Codetext
 | H2 Ebene +3 | WA-LB | 1255Wa 0811561861 | yes | Codetext | m² | Trockenbauarbeiten | Wand | Außenwand 7-Schalig | WA-LB | 0 | A | 11.25 | 1255HWa0000000073 | NEW | no | yes | 0 | 0 | no | 0 | no | Codetext
 | H2 Ebene +3 | WA-KL | 1255Wa 0811561862 | yes | Codetext | m² | Zimmer- und Holzbauarbeiten | Wand | Außenwand 7-Schalig | WA-KL | 0 | A | 11.25 | 1255HWa0000000073 | NEW | no | yes | 0 | 0 | no | 0 | no | Codetext
 | H2 Ebene +3 | WA-TL | 1255Wa 0811561863 | yes | Codetext | m² | Zimmer- und Holzbauarbeiten | Wand | Außenwand 7-Schalig | WA-TL | 0 | A | 11.25 | 1255HWa0000000073 | NEW | no | yes | 0 | 0 | no | 0 | no | Codetext
 | H2 Ebene +3 | WA-HS | 1255Wa 0811561864 | yes | Codetext | m² | Zimmer- und Holzbauarbeiten | Wand | Außenwand 7-Schalig | WA-HS | 0 | A | 11.25 | 1255HWa0000000073 | NEW | no | yes | 0 | 0 | no | 0 | no | Codetext
 | H2 Ebene +3 | WA-LB | 1255Wa 0811561753 | yes | Codetext | m² | Trockenbauarbeiten | Wand | Außenwand 7-Schalig | WA-LB | 0 | A | 11.25 | 1255HWa0000000073 | NEW | no | yes | 0 | 0 | no | 0 | no | Codetext
 | H2 Ebene +3 | WA-DL | 1255Wa 0811561754 | yes | Codetext | m³ | Zimmer- und Holzbauarbeiten | Wand | Außenwand 7-Schalig | WA-DL | 0 | A | 11.25 | 1255HWa0000000073 | NEW | no | yes | 0 | 0 | no | 0 | no | Codetext | AllplanAttributes - ash D_Detailverweis: DT D; ash D_Plannummer: D1851
 | H2 Ebene +3 | WA-DL | 1255Wa 0811561755 | yes | Codetext | m³ | Zimmer- und Holzbauarbeiten | Wand | Außenwand 7-Schalig | WA-DL | 0 | A | 11.25 | 1255HWa0000000073 | NEW | no | yes | 0 | 0 | no | 0 | no | Codetext
 | H2 Ebene +3 | WA-LB | 1255Wa 0811561756 | yes | Codetext | m² | Trockenbauarbeiten | Wand | Außenwand 7-Schalig | WA-LB | 0 | A | 11.25 | 1255HWa0000000073 | NEW | no | yes | 0 | 0 | no | 0 | no | Codetext
 | H2 Ebene +3 | WA-KL | 1255Wa 0811561757 | yes | Codetext | m² | Zimmer- und Holzbauarbeiten | Wand | Außenwand 7-Schalig | WA-KL | 0 | A | 11.25 | 1255HWa0000000073 | NEW | no | yes | 0 | 0 | no | 0 | no | Codetext
 | H2 Ebene +3 | WA-TL | 1255Wa 0811561758 | yes | Codetext | m² | Zimmer- und Holzbauarbeiten | Wand | Außenwand 7-Schalig | WA-TL | 0 | A | 11.25 | 1255HWa0000000073 | NEW | no | yes | 0 | 0 | no | 0 | no | Codetext
 | H2 Ebene +3 | WA-HS | 1255Wa 0811561759 | yes | Codetext | m² | Zimmer- und Holzbauarbeiten | Wand | Außenwand 7-Schalig | WA-HS | 0 | A | 11.25 | 1255HWa0000000073 | NEW | no | yes | 0 | 0 | no | 0 | no | Codetext
 | H2 Ebene +3 | WA-LB | 1255Wa 0811568241 | yes | Codetext | m² | Trockenbauarbeiten | Wand | Außenwand 7-Schalig | WA-LB | 0 | A | 11.25 | 1255HWa0000000073 | NEW | no | yes | 0 | 0 | no | 0 | no | Codetext
 | H2 Ebene +3 | WA-DL | 1255Wa 0811568242 | yes | Codetext | m³ | Zimmer- und Holzbauarbeiten | Wand | Außenwand 7-Schalig | WA-DL | 0 | A | 11.25 | 1255HWa0000000073 | NEW | no | yes | 0 | 0 | no | 0 | no | Codetext | AllplanAttributes - ash D_Detailverweis: DT D; ash D_Plannummer: D1851
 | H2 Ebene +3 | WA-DL | 1255Wa 0811568243 | yes | Codetext | m³ | Zimmer- und Holzbauarbeiten | Wand | Außenwand 7-Schalig | WA-DL | 0 | A | 11.25 | 1255HWa0000000073 | NEW | no | yes | 0 | 0 | no | 0 | no | Codetext
 | H2 Ebene +3 | WA-LB | 1255Wa 0811568244 | yes | Codetext | m² | Trockenbauarbeiten | Wand | Außenwand 7-Schalig | WA-LB | 0 | A | 11.25 | 1255HWa0000000073 | NEW | no | yes | 0 | 0 | no | 0 | no | Codetext
 | H2 Ebene +3 | WA-KL | 1255Wa 0811568245 | yes | Codetext | m² | Zimmer- und Holzbauarbeiten | Wand | Außenwand 7-Schalig | WA-KL | 0 | A | 11.25 | 1255HWa0000000073 | NEW | no | yes | 0 | 0 | no | 0 | no | Codetext
 | H2 Ebene +3 | WA-TL | 1255Wa 0811568246 | yes | Codetext | m² | Zimmer- und Holzbauarbeiten | Wand | Außenwand 7-Schalig | WA-TL | 0 | A | 11.25 | 1255HWa0000000073 | NEW | no | yes | 0 | 0 | no | 0 | no | Codetext
 | H2 Ebene +3 | WA-HS | 1255Wa 0811568247 | yes | Codetext | m² | Zimmer- und Holzbauarbeiten | Wand | Außenwand 7-Schalig | WA-HS | 0 | A | 11.25 | 1255HWa0000000073 | NEW | no | yes | 0 | 0 | no | 0 | no | Codetext
 | H2 Ebene +3 | WA-LB | 1255Wa 0811562056 | yes | Codetext | m² | Trockenbauarbeiten | Wand | Außenwand 7-Schalig | WA-LB | 0 | A | 11.25 | 1255HWa0000000073 | NEW | no | yes | 0 | 0 | no | 0 | no | Codetext
 | H2 Ebene +3 | WA-DL | 1255Wa 0811562057 | yes | Codetext | m³ | Zimmer- und Holzbauarbeiten | Wand | Außenwand 7-Schalig | WA-DL | 0 | A | 11.25 | 1255HWa0000000073 | NEW | no | yes | 0 | 0 | no | 0 | no | Codetext | AllplanAttributes - ash D_Detailverweis: DT D; ash D_Plannummer: D1851
 | H2 Ebene +3 | WA-DL | 1255Wa 0811562058 | yes | Codetext | m³ | Zimmer- und Holzbauarbeiten | Wand | Außenwand 7-Schalig | WA-DL | 0 | A | 11.25 | 1255HWa0000000073 | NEW | no | yes | 0 | 0 | no | 0 | no | Codetext
 | H2 Ebene +3 | WA-LB | 1255Wa 0811562059 | yes | Codetext | m² | Trockenbauarbeiten | Wand | Außenwand 7-Schalig | WA-LB | 0 | A | 11.25 | 1255HWa0000000073 | NEW | no | yes | 0 | 0 | no | 0 | no | Codetext
 | H2 Ebene +3 | WA-KL | 1255Wa 0811562060 | yes | Codetext | m² | Zimmer- und Holzbauarbeiten | Wand | Außenwand 7-Schalig | WA-KL | 0 | A | 11.25 | 1255HWa0000000073 | NEW | no | yes | 0 | 0 | no | 0 | no | Codetext
 | H2 Ebene +3 | WA-TL | 1255Wa 0811562061 | yes | Codetext | m² | Zimmer- und Holzbauarbeiten | Wand | Außenwand 7-Schalig | WA-TL | 0 | A | 11.25 | 1255HWa0000000073 | NEW | no | yes | 0 | 0 | no | 0 | no | Codetext
 | H2 Ebene +3 | WA-HS | 1255Wa 0811562062 | yes | Codetext | m² | Zimmer- und Holzbauarbeiten | Wand | Außenwand 7-Schalig | WA-HS | 0 | A | 11.25 | 1255HWa0000000073 | NEW | no | yes | 0 | 0 | no | 0 | no | Codetext
 | H2 Ebene +3 | WA-LB | 1255Wa 0811568800 | yes | Codetext | m² | Trockenbauarbeiten | Wand | Attika | WA-LB |  | A |  |  | NEW | no | yes |  | 0 | no |  | no | Codetext
 | H2 Ebene +3 | WA-DL | 1255Wa 0811568798 | yes | Codetext | m³ | Zimmer- und Holzbauarbeiten | Wand | Attika | WA-DL |  | A |  |  | NEW | no | yes |  | 0 | no |  | no | Codetext
Dämmung | H2 Ebene +3 | WA-DL | 1255Wa 0811568796 | yes | Codetext | m² | Zimmer- und Holzbauarbeiten | Wand | Dämmung | WA-DL |  | A |  |  | NEW | no | yes |  | 0 | no |  | no | Codetext
Fassadenschicht (außen) | H2 Ebene +3 | WA-F | 1255Wa 0811568802 | yes | Codetext | m² | Zimmer- und Holzbauarbeiten | Wand | Fassadenschicht (außen) | WA-F |  | A |  |  | NEW | no | yes |  | 0 | no |  | no | Codetext
 | H2 Ebene +3 | WA-LB | 1255Wa 0811568810 | yes | Codetext | m² | Trockenbauarbeiten | Wand | Attika | WA-LB |  | A |  |  | NEW | no | yes |  | 0 | no |  | no | Codetext
 | H2 Ebene +3 | WA-DL | 1255Wa 0811568808 | yes | Codetext | m³ | Zimmer- und Holzbauarbeiten | Wand | Attika | WA-DL |  | A |  |  | NEW | no | yes |  | 0 | no |  | no | Codetext
Dämmung | H2 Ebene +3 | WA-DL | 1255Wa 0811568806 | yes | Codetext | m² | Zimmer- und Holzbauarbeiten | Wand | Dämmung | WA-DL |  | A |  |  | NEW | no | yes |  | 0 | no |  | no | Codetext
Fassadenschicht (außen) | H2 Ebene +3 | WA-F | 1255Wa 0811568812 | yes | Codetext | m² | Zimmer- und Holzbauarbeiten | Wand | Fassadenschicht (außen) | WA-F |  | A |  |  | NEW | no | yes |  | 0 | no |  | no | Codetext
 | H2 Ebene +3 | WA-LB | 1255Wa 0000001674 | yes | Codetext | m² | Trockenbauarbeiten | Wand | Außenwand 7-Schalig | WA-LB | 0 | A | 11.25 | 1255HWa0000001569 | NEW | no | yes | 0 | 0 | no | 0 | no | Codetext
 | H2 Ebene +3 | WA-DL | 1255Wa 0000001680 | yes | Codetext | m³ | Zimmer- und Holzbauarbeiten | Wand | Außenwand 7-Schalig | WA-DL | 0 | A | 11.25 | 1255HWa0000001569 | NEW | no | yes | 0 | 0 | no | 0 | no | Codetext
 | H2 Ebene +3 | WA-DL | 1255Wa 0000001686 | yes | Codetext | m³ | Zimmer- und Holzbauarbeiten | Wand | Außenwand 7-Schalig | WA-DL | 0 | A | 11.25 | 1255HWa0000001569 | NEW | no | yes | 0 | 0 | no | 0 | no | Codetext
 | H2 Ebene +3 | WA-LB | 1255Wa 0000001692 | yes | Codetext | m² | Trockenbauarbeiten | Wand | Außenwand 7-Schalig | WA-LB | 0 | A | 11.25 | 1255HWa0000001569 | NEW | no | yes | 0 | 0 | no | 0 | no | Codetext
 | H2 Ebene +3 | WA-KL | 1255Wa 0000001698 | yes | Codetext | m² | Zimmer- und Holzbauarbeiten | Wand | Außenwand 7-Schalig | WA-KL | 0 | A | 11.25 | 1255HWa0000001569 | NEW | no | yes | 0 | 0 | no | 0 | no | Codetext
 | H2 Ebene +3 | WA-TL | 1255Wa 0000001704 | yes | Codetext | m² | Zimmer- und Holzbauarbeiten | Wand | Außenwand 7-Schalig | WA-TL | 0 | A | 11.25 | 1255HWa0000001569 | NEW | no | yes | 0 | 0 | no | 0 | no | Codetext
 | H2 Ebene +3 | WA-HS | 1255Wa 0000001710 | yes | Codetext | m² | Zimmer- und Holzbauarbeiten | Wand | Außenwand 7-Schalig | WA-HS | 0 | A | 11.25 | 1255HWa0000001569 | NEW | no | yes | 0 | 0 | no | 0 | no | Codetext
 | H2 Ebene +3 | WA-LB | 1255Wa 0811567551 | yes | Codetext | m² | Trockenbauarbeiten | Wand | Außenwand 7-Schalig | WA-LB | 0 | A | 11.25 | 1255HWa0000000073 | NEW | no | yes | 0 | 0 | no | 0 | no | Codetext
 | H2 Ebene +3 | WA-DL | 1255Wa 0811567550 | yes | Codetext | m³ | Zimmer- und Holzbauarbeiten | Wand | Außenwand 7-Schalig | WA-DL | 0 | A | 11.25 | 1255HWa0000000073 | NEW | no | yes | 0 | 0 | no | 0 | no | Codetext | AllplanAttributes - ash D_Detailverweis: DT D; ash D_Plannummer: D1851
 | H2 Ebene +3 | WA-DL | 1255Wa 0811567549 | yes | Codetext | m³ | Zimmer- und Holzbauarbeiten | Wand | Außenwand 7-Schalig | WA-DL | 0 | A | 11.25 | 1255HWa0000000073 | NEW | no | yes | 0 | 0 | no | 0 | no | Codetext
 | H2 Ebene +3 | WA-LB | 1255Wa 0811567548 | yes | Codetext | m² | Trockenbauarbeiten | Wand | Außenwand 7-Schalig | WA-LB | 0 | A | 11.25 | 1255HWa0000000073 | NEW | no | yes | 0 | 0 | no | 0 | no | Codetext
 | H2 Ebene +3 | WA-KL | 1255Wa 0811567547 | yes | Codetext | m² | Zimmer- und Holzbauarbeiten | Wand | Außenwand 7-Schalig | WA-KL | 0 | A | 11.25 | 1255HWa0000000073 | NEW | no | yes | 0 | 0 | no | 0 | no | Codetext
 | H2 Ebene +3 | WA-TL | 1255Wa 0811567546 | yes | Codetext | m² | Zimmer- und Holzbauarbeiten | Wand | Außenwand 7-Schalig | WA-TL | 0 | A | 11.25 | 1255HWa0000000073 | NEW | no | yes | 0 | 0 | no | 0 | no | Codetext
 | H2 Ebene +3 | WA-HS | 1255Wa 0811567545 | yes | Codetext | m² | Zimmer- und Holzbauarbeiten | Wand | Außenwand 7-Schalig | WA-HS | 0 | A | 11.25 | 1255HWa0000000073 | NEW | no | yes | 0 | 0 | no | 0 | no | Codetext
 | H2 Ebene +3 | WA-LB | 1255Wa 0811561990 | yes | Codetext | m² | Trockenbauarbeiten | Wand | Außenwand 7-Schalig | WA-LB | 0 | A | 11.25 | 1255HWa0000000073 | NEW | no | yes | 0 | 0 | no | 0 | no | Codetext
 | H2 Ebene +3 | WA-DL | 1255Wa 0811561991 | yes | Codetext | m³ | Zimmer- und Holzbauarbeiten | Wand | Außenwand 7-Schalig | WA-DL | 0 | A | 11.25 | 1255HWa0000000073 | NEW | no | yes | 0 | 0 | no | 0 | no | Codetext | AllplanAttributes - ash D_Detailverweis: DT D; ash D_Plannummer: D1851
 | H2 Ebene +3 | WA-DL | 1255Wa 0811561992 | yes | Codetext | m³ | Zimmer- und Holzbauarbeiten | Wand | Außenwand 7-Schalig | WA-DL | 0 | A | 11.25 | 1255HWa0000000073 | NEW | no | yes | 0 | 0 | no | 0 | no | Codetext
 | H2 Ebene +3 | WA-LB | 1255Wa 0811561993 | yes | Codetext | m² | Trockenbauarbeiten | Wand | Außenwand 7-Schalig | WA-LB | 0 | A | 11.25 | 1255HWa0000000073 | NEW | no | yes | 0 | 0 | no | 0 | no | Codetext
 | H2 Ebene +3 | WA-KL | 1255Wa 0811561994 | yes | Codetext | m² | Zimmer- und Holzbauarbeiten | Wand | Außenwand 7-Schalig | WA-KL | 0 | A | 11.25 | 1255HWa0000000073 | NEW | no | yes | 0 | 0 | no | 0 | no | Codetext
 | H2 Ebene +3 | WA-TL | 1255Wa 0811561995 | yes | Codetext | m² | Zimmer- und Holzbauarbeiten | Wand | Außenwand 7-Schalig | WA-TL | 0 | A | 11.25 | 1255HWa0000000073 | NEW | no | yes | 0 | 0 | no | 0 | no | Codetext
 | H2 Ebene +3 | WA-HS | 1255Wa 0811561996 | yes | Codetext | m² | Zimmer- und Holzbauarbeiten | Wand | Außenwand 7-Schalig | WA-HS | 0 | A | 11.25 | 1255HWa0000000073 | NEW | no | yes | 0 | 0 | no | 0 | no | Codetext
 | H2 Ebene +3 | WA-LB | 1255Wa 0811569624 | yes | Codetext | m² | Trockenbauarbeiten | Wand | Außenwand 7-Schalig | WA-LB | 0 | A | 11.25 | 1255HWa0000000073 | NEW | no | yes | 0 | 0 | no | 0 | no | Codetext
 | H2 Ebene +3 | WA-DL | 1255Wa 0811569625 | yes | Codetext | m³ | Zimmer- und Holzbauarbeiten | Wand | Außenwand 7-Schalig | WA-DL | 0 | A | 11.25 | 1255HWa0000000073 | NEW | no | yes | 0 | 0 | no | 0 | no | Codetext | AllplanAttributes - ash D_Detailverweis: DT D; ash D_Plannummer: D1851
 | H2 Ebene +3 | WA-DL | 1255Wa 0811569626 | yes | Codetext | m³ | Zimmer- und Holzbauarbeiten | Wand | Außenwand 7-Schalig | WA-DL | 0 | A | 11.25 | 1255HWa0000000073 | NEW | no | yes | 0 | 0 | no | 0 | no | Codetext
 | H2 Ebene +3 | WA-DL | 1255Wa 0811569627 | yes | Codetext | m³ | Zimmer- und Holzbauarbeiten | Wand | Außenwand 7-Schalig | WA-DL | 0 | A | 11.25 | 1255HWa0000000073 | NEW | no | yes | 0 | 0 | no | 0 | no | Codetext
 | H2 Ebene +3 | WA-LB | 1255Wa 0811569628 | yes | Codetext | m² | Trockenbauarbeiten | Wand | Außenwand 7-Schalig | WA-LB | 0 | A | 11.25 | 1255HWa0000000073 | NEW | no | yes | 0 | 0 | no | 0 | no | Codetext
 | H2 Ebene +3 | WA-KL | 1255Wa 0811569629 | yes | Codetext | m² | Zimmer- und Holzbauarbeiten | Wand | Außenwand 7-Schalig | WA-KL | 0 | A | 11.25 | 1255HWa0000000073 | NEW | no | yes | 0 | 0 | no | 0 | no | Codetext
 | H2 Ebene +3 | WA-TL | 1255Wa 0811569630 | yes | Codetext | m² | Zimmer- und Holzbauarbeiten | Wand | Außenwand 7-Schalig | WA-TL | 0 | A | 11.25 | 1255HWa0000000073 | NEW | no | yes | 0 | 0 | no | 0 | no | Codetext
 | H2 Ebene +3 | WA-HS | 1255Wa 0811569631 | yes | Codetext | m² | Zimmer- und Holzbauarbeiten | Wand | Außenwand 7-Schalig | WA-HS | 0 | A | 11.25 | 1255HWa0000000073 | NEW | no | yes | 0 | 0 | no | 0 | no | Codetext
 | H2 Ebene +3 | WA-LB | 1255Wa 0811569703 | yes | Codetext | m² | Trockenbauarbeiten | Wand | Außenwand 7-Schalig | WA-LB | 0 | A | 11.25 | 1255HWa0000000073 | NEW | no | yes | 0 | 0 | no | 0 | no | Codetext
 | H2 Ebene +3 | WA-DL | 1255Wa 0811569704 | yes | Codetext | m³ | Zimmer- und Holzbauarbeiten | Wand | Außenwand 7-Schalig | WA-DL | 0 | A | 11.25 | 1255HWa0000000073 | NEW | no | yes | 0 | 0 | no | 0 | no | Codetext | AllplanAttributes - ash D_Detailverweis: DT D; ash D_Plannummer: D1851
 | H2 Ebene +3 | WA-DL | 1255Wa 0811569705 | yes | Codetext | m³ | Zimmer- und Holzbauarbeiten | Wand | Außenwand 7-Schalig | WA-DL | 0 | A | 11.25 | 1255HWa0000000073 | NEW | no | yes | 0 | 0 | no | 0 | no | Codetext
 | H2 Ebene +3 | WA-LB | 1255Wa 0811569706 | yes | Codetext | m² | Trockenbauarbeiten | Wand | Außenwand 7-Schalig | WA-LB | 0 | A | 11.25 | 1255HWa0000000073 | NEW | no | yes | 0 | 0 | no | 0 | no | Codetext
 | H2 Ebene +3 | WA-KL | 1255Wa 0811569707 | yes | Codetext | m² | Zimmer- und Holzbauarbeiten | Wand | Außenwand 7-Schalig | WA-KL | 0 | A | 11.25 | 1255HWa0000000073 | NEW | no | yes | 0 | 0 | no | 0 | no | Codetext
 | H2 Ebene +3 | WA-TL | 1255Wa 0811569708 | yes | Codetext | m² | Zimmer- und Holzbauarbeiten | Wand | Außenwand 7-Schalig | WA-TL | 0 | A | 11.25 | 1255HWa0000000073 | NEW | no | yes | 0 | 0 | no | 0 | no | Codetext
 | H2 Ebene +3 | WA-HS | 1255Wa 0811569709 | yes | Codetext | m² | Zimmer- und Holzbauarbeiten | Wand | Außenwand 7-Schalig | WA-HS | 0 | A | 11.25 | 1255HWa0000000073 | NEW | no | yes | 0 | 0 | no | 0 | no | Codetext
 | H2 Ebene +3 | WA-LB | 1255Wa 0811569828 | yes | Codetext | m² | Trockenbauarbeiten | Wand | Außenwand 7-Schalig | WA-LB | 0 | A | 11.25 | 1255HWa0000000073 | NEW | no | yes | 0 | 0 | no | 0 | no | Codetext
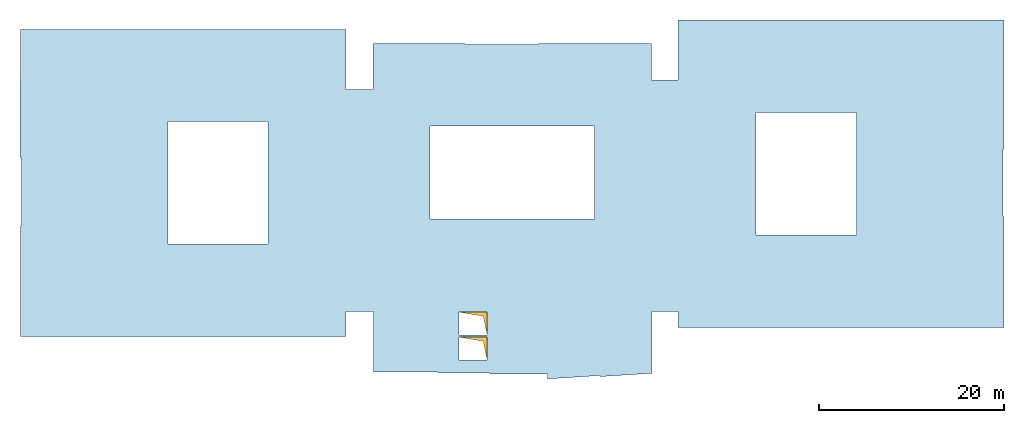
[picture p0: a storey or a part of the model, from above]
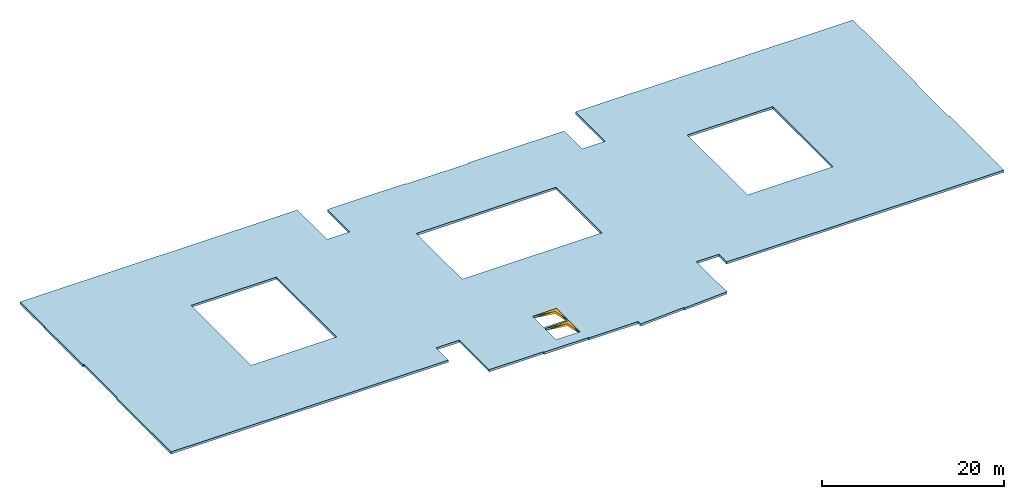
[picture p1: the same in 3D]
Properties of the parts of a building model (IFC4), part 47 of 80

# IfcWall (6826)
Name | In | Material | Allright_Bauteil_ID | 2D Interaktion | Codetext | Abrechnungsart | Gewerk | Objektname | Bezeichnung | AllplanAttributes, Material | Typ = SurfaceSpreadOfFlame | Brandschutzklasse | OKFF | P_ID | Status | LoadBearing | IsExternal | FireRating | ThermalTransmittance (W/K/m2) | Combustible | AcousticRating | Compartmentation | Reference
 | H2 Ebene +3 | WA-DL | 1255Wa 0811569829 | yes | Codetext | m³ | Zimmer- und Holzbauarbeiten | Wand | Außenwand 7-Schalig | WA-DL | 0 | A | 11.25 | 1255HWa0000000073 | NEW | no | yes | 0 | 0 | no | 0 | no | Codetext | AllplanAttributes - ash D_Detailverweis: DT D; ash D_Plannummer: D1851
 | H2 Ebene +3 | WA-DL | 1255Wa 0811569830 | yes | Codetext | m³ | Zimmer- und Holzbauarbeiten | Wand | Außenwand 7-Schalig | WA-DL | 0 | A | 11.25 | 1255HWa0000000073 | NEW | no | yes | 0 | 0 | no | 0 | no | Codetext
 | H2 Ebene +3 | WA-LB | 1255Wa 0811569831 | yes | Codetext | m² | Trockenbauarbeiten | Wand | Außenwand 7-Schalig | WA-LB | 0 | A | 11.25 | 1255HWa0000000073 | NEW | no | yes | 0 | 0 | no | 0 | no | Codetext
 | H2 Ebene +3 | WA-KL | 1255Wa 0811569832 | yes | Codetext | m² | Zimmer- und Holzbauarbeiten | Wand | Außenwand 7-Schalig | WA-KL | 0 | A | 11.25 | 1255HWa0000000073 | NEW | no | yes | 0 | 0 | no | 0 | no | Codetext
 | H2 Ebene +3 | WA-TL | 1255Wa 0811569833 | yes | Codetext | m² | Zimmer- und Holzbauarbeiten | Wand | Außenwand 7-Schalig | WA-TL | 0 | A | 11.25 | 1255HWa0000000073 | NEW | no | yes | 0 | 0 | no | 0 | no | Codetext
 | H2 Ebene +3 | WA-HS | 1255Wa 0811569834 | yes | Codetext | m² | Zimmer- und Holzbauarbeiten | Wand | Außenwand 7-Schalig | WA-HS | 0 | A | 11.25 | 1255HWa0000000073 | NEW | no | yes | 0 | 0 | no | 0 | no | Codetext
 | H2 Ebene +3 | WA-LB | 1255Wa 0811562341 | yes | Codetext | m² | Trockenbauarbeiten | Wand | Außenwand 7-Schalig | WA-LB | 0 | A | 11.25 | 1255HWa0000000073 | NEW | no | yes | 0 | 0 | no | 0 | no | Codetext
 | H2 Ebene +3 | WA-DL | 1255Wa 0811562342 | yes | Codetext | m³ | Zimmer- und Holzbauarbeiten | Wand | Außenwand 7-Schalig | WA-DL | 0 | A | 11.25 | 1255HWa0000000073 | NEW | no | yes | 0 | 0 | no | 0 | no | Codetext | AllplanAttributes - ash D_Detailverweis: DT D; ash D_Plannummer: D1851
 | H2 Ebene +3 | WA-DL | 1255Wa 0811562343 | yes | Codetext | m³ | Zimmer- und Holzbauarbeiten | Wand | Außenwand 7-Schalig | WA-DL | 0 | A | 11.25 | 1255HWa0000000073 | NEW | no | yes | 0 | 0 | no | 0 | no | Codetext
 | H2 Ebene +3 | WA-LB | 1255Wa 0811562344 | yes | Codetext | m² | Trockenbauarbeiten | Wand | Außenwand 7-Schalig | WA-LB | 0 | A | 11.25 | 1255HWa0000000073 | NEW | no | yes | 0 | 0 | no | 0 | no | Codetext
 | H2 Ebene +3 | WA-KL | 1255Wa 0811562345 | yes | Codetext | m² | Zimmer- und Holzbauarbeiten | Wand | Außenwand 7-Schalig | WA-KL | 0 | A | 11.25 | 1255HWa0000000073 | NEW | no | yes | 0 | 0 | no | 0 | no | Codetext
 | H2 Ebene +3 | WA-TL | 1255Wa 0811562346 | yes | Codetext | m² | Zimmer- und Holzbauarbeiten | Wand | Außenwand 7-Schalig | WA-TL | 0 | A | 11.25 | 1255HWa0000000073 | NEW | no | yes | 0 | 0 | no | 0 | no | Codetext
 | H2 Ebene +3 | WA-HS | 1255Wa 0811562347 | yes | Codetext | m² | Zimmer- und Holzbauarbeiten | Wand | Außenwand 7-Schalig | WA-HS | 0 | A | 11.25 | 1255HWa0000000073 | NEW | no | yes | 0 | 0 | no | 0 | no | Codetext
 | H2 Ebene +3 | WA-LB | 1255Wa 0811562275 | yes | Codetext | m² | Trockenbauarbeiten | Wand | Außenwand 7-Schalig | WA-LB | 0 | A | 11.25 | 1255HWa0000000073 | NEW | no | yes | 0 | 0 | no | 0 | no | Codetext
 | H2 Ebene +3 | WA-DL | 1255Wa 0811562276 | yes | Codetext | m³ | Zimmer- und Holzbauarbeiten | Wand | Außenwand 7-Schalig | WA-DL | 0 | A | 11.25 | 1255HWa0000000073 | NEW | no | yes | 0 | 0 | no | 0 | no | Codetext | AllplanAttributes - ash D_Detailverweis: DT D; ash D_Plannummer: D1851
 | H2 Ebene +3 | WA-DL | 1255Wa 0811562277 | yes | Codetext | m³ | Zimmer- und Holzbauarbeiten | Wand | Außenwand 7-Schalig | WA-DL | 0 | A | 11.25 | 1255HWa0000000073 | NEW | no | yes | 0 | 0 | no | 0 | no | Codetext
 | H2 Ebene +3 | WA-LB | 1255Wa 0811562278 | yes | Codetext | m² | Trockenbauarbeiten | Wand | Außenwand 7-Schalig | WA-LB | 0 | A | 11.25 | 1255HWa0000000073 | NEW | no | yes | 0 | 0 | no | 0 | no | Codetext
 | H2 Ebene +3 | WA-KL | 1255Wa 0811562279 | yes | Codetext | m² | Zimmer- und Holzbauarbeiten | Wand | Außenwand 7-Schalig | WA-KL | 0 | A | 11.25 | 1255HWa0000000073 | NEW | no | yes | 0 | 0 | no | 0 | no | Codetext
 | H2 Ebene +3 | WA-TL | 1255Wa 0811562280 | yes | Codetext | m² | Zimmer- und Holzbauarbeiten | Wand | Außenwand 7-Schalig | WA-TL | 0 | A | 11.25 | 1255HWa0000000073 | NEW | no | yes | 0 | 0 | no | 0 | no | Codetext
 | H2 Ebene +3 | WA-HS | 1255Wa 0811562281 | yes | Codetext | m² | Zimmer- und Holzbauarbeiten | Wand | Außenwand 7-Schalig | WA-HS | 0 | A | 11.25 | 1255HWa0000000073 | NEW | no | yes | 0 | 0 | no | 0 | no | Codetext
2x Gipsfaserplatte | H2 Ebene +3 | WA-LB | 1255Wa 0811562928 | yes |  | m² | Trockenbauarbeiten | Wand | 2x Gipsfaserplatte | WA-LB |  |  | 11.25 | 1255HWa0811453583 | NEW | no | yes | REI 60-A1 - D,s2-d0 +A1
2x Gipsfaserplatte | H2 Ebene +3 | WA-LB | 1255Wa 0811562929 | yes |  | m² | Trockenbauarbeiten | Wand | 2x Gipsfaserplatte | WA-LB |  |  | 11.25 | 1255HWa0811453583 | NEW | no | yes | 0 | 0.9 |  | 32 | AllplanAttributes - Sicherheitsklasse: -; Sonnenschutztyp: Movable; g-Wert: 0,51
Holzständer + Zwischendämmung | H2 Ebene +3 | WA-HD | 1255Wa 0811562930 | yes |  | m³ | Zimmer- und Holzbauarbeiten | Wand | Holzständer + Zwischendämmung | WA-HD |  |  | 11.25 | 1255HWa0811453583 | NEW | no | yes | REI 60-A1 - D,s2-d0 +A1 | AllplanAttributes - ash D_Detailverweis: DT A; ash D_Plannummer: D1850
 | H2 Ebene +3 | WA-LB | 1255Wa 0811562931 | yes | Codetext | m² | Trockenbauarbeiten | Wand | Außenwand 7-Schalig | WA-LB | 0 | A | 11.25 | 1255HWa0811453583 | NEW | no | yes | 0 | 0.9 | no | 32 | no | Codetext | AllplanAttributes - Sicherheitsklasse: -; Sonnenschutztyp: Movable; g-Wert: 0,51
 | H2 Ebene +3 | WA-LB | 1255Wa 0811562932 | yes | Codetext | m² | Trockenbauarbeiten | Wand | Außenwand 7-Schalig | WA-LB | 0 | A | 11.25 | 1255HWa0811453583 | NEW | no | yes | 0 | 0 | no | 0 | no | Codetext
Staffel + Zwischendämmung | H2 Ebene +3 | WA-DL | 1255Wa 0811562933 | yes |  | m³ | Zimmer- und Holzbauarbeiten | Wand | Staffel + Zwischendämmung | WA-DL |  |  | 11.25 | 1255HWa0811453583 | NEW | no | yes | REI 60-A1 - D,s2-d0 +A1
Konterlattung | H2 Ebene +3 | WA-KL | 1255Wa 0811562934 | yes |  | m² | Zimmer- und Holzbauarbeiten | Wand | Konterlattung | WA-KL |  |  | 11.25 | 1255HWa0811453583 | NEW | no | yes | REI 60-A1 - D,s2-d0 +A1
Traglattung | H2 Ebene +3 | WA-TL | 1255Wa 0811562935 | yes |  | m² | Zimmer- und Holzbauarbeiten | Wand | Traglattung | WA-TL |  |  | 11.25 | 1255HWa0811453583 | NEW | no | yes | REI 60-A1 - D,s2-d0 +A1
Holzschindel | H2 Ebene +3 | WA-HS | 1255Wa 0811562936 | yes |  | m² | Zimmer- und Holzbauarbeiten | Wand | Holzschindel | WA-HS |  |  | 11.25 | 1255HWa0811453583 | NEW | no | yes | REI 60-A1 - D,s2-d0 +A1 | AllplanAttributes - ash D_Detailverweis: DT 4; ash D_Plannummer: D1615
 | H2 Ebene +3 | WA-LB | 1255Wa 0811566970 | yes | Codetext | m² | Trockenbauarbeiten | Wand | Außenwand 7-Schalig | WA-LB | 0 | A | 11.25 | 1255HWa0000000073 | NEW | no | yes | 0 | 0 | no | 0 | no | Codetext
 | H2 Ebene +3 | WA-DL | 1255Wa 0811566971 | yes | Codetext | m³ | Zimmer- und Holzbauarbeiten | Wand | Außenwand 7-Schalig | WA-DL | 0 | A | 11.25 | 1255HWa0000000073 | NEW | no | yes | 0 | 0 | no | 0 | no | Codetext | AllplanAttributes - ash D_Detailverweis: DT D; ash D_Plannummer: D1851
 | H2 Ebene +3 | WA-DL | 1255Wa 0811566972 | yes | Codetext | m³ | Zimmer- und Holzbauarbeiten | Wand | Außenwand 7-Schalig | WA-DL | 0 | A | 11.25 | 1255HWa0000000073 | NEW | no | yes | 0 | 0 | no | 0 | no | Codetext
 | H2 Ebene +3 | WA-LB | 1255Wa 0811566973 | yes | Codetext | m² | Trockenbauarbeiten | Wand | Außenwand 7-Schalig | WA-LB | 0 | A | 11.25 | 1255HWa0000000073 | NEW | no | yes | 0 | 0 | no | 0 | no | Codetext
 | H2 Ebene +3 | WA-KL | 1255Wa 0811566974 | yes | Codetext | m² | Zimmer- und Holzbauarbeiten | Wand | Außenwand 7-Schalig | WA-KL | 0 | A | 11.25 | 1255HWa0000000073 | NEW | no | yes | 0 | 0 | no | 0 | no | Codetext
 | H2 Ebene +3 | WA-TL | 1255Wa 0811566975 | yes | Codetext | m² | Zimmer- und Holzbauarbeiten | Wand | Außenwand 7-Schalig | WA-TL | 0 | A | 11.25 | 1255HWa0000000073 | NEW | no | yes | 0 | 0 | no | 0 | no | Codetext
 | H2 Ebene +3 | WA-HS | 1255Wa 0811566976 | yes | Codetext | m² | Zimmer- und Holzbauarbeiten | Wand | Außenwand 7-Schalig | WA-HS | 0 | A | 11.25 | 1255HWa0000000073 | NEW | no | yes | 0 | 0 | no | 0 | no | Codetext
 | H2 Ebene +3 | WA-LB | 1255Wa 0811562126 | yes | Codetext | m² | Trockenbauarbeiten | Wand | Außenwand 7-Schalig | WA-LB | 0 | A | 11.25 | 1255HWa0000000073 | NEW | no | yes | 0 | 0 | no | 0 | no | Codetext
 | H2 Ebene +3 | WA-DL | 1255Wa 0811562127 | yes | Codetext | m³ | Zimmer- und Holzbauarbeiten | Wand | Außenwand 7-Schalig | WA-DL | 0 | A | 11.25 | 1255HWa0000000073 | NEW | no | yes | 0 | 0 | no | 0 | no | Codetext | AllplanAttributes - ash D_Detailverweis: DT D; ash D_Plannummer: D1851
 | H2 Ebene +3 | WA-DL | 1255Wa 0811562128 | yes | Codetext | m³ | Zimmer- und Holzbauarbeiten | Wand | Außenwand 7-Schalig | WA-DL | 0 | A | 11.25 | 1255HWa0000000073 | NEW | no | yes | 0 | 0 | no | 0 | no | Codetext
 | H2 Ebene +3 | WA-LB | 1255Wa 0811562129 | yes | Codetext | m² | Trockenbauarbeiten | Wand | Außenwand 7-Schalig | WA-LB | 0 | A | 11.25 | 1255HWa0000000073 | NEW | no | yes | 0 | 0 | no | 0 | no | Codetext
 | H2 Ebene +3 | WA-KL | 1255Wa 0811562130 | yes | Codetext | m² | Zimmer- und Holzbauarbeiten | Wand | Außenwand 7-Schalig | WA-KL | 0 | A | 11.25 | 1255HWa0000000073 | NEW | no | yes | 0 | 0 | no | 0 | no | Codetext
 | H2 Ebene +3 | WA-TL | 1255Wa 0811562131 | yes | Codetext | m² | Zimmer- und Holzbauarbeiten | Wand | Außenwand 7-Schalig | WA-TL | 0 | A | 11.25 | 1255HWa0000000073 | NEW | no | yes | 0 | 0 | no | 0 | no | Codetext
 | H2 Ebene +3 | WA-HS | 1255Wa 0811562132 | yes | Codetext | m² | Zimmer- und Holzbauarbeiten | Wand | Außenwand 7-Schalig | WA-HS | 0 | A | 11.25 | 1255HWa0000000073 | NEW | no | yes | 0 | 0 | no | 0 | no | Codetext
 | H2 Ebene +3 | WA-LB | 1255Wa 0811569073 | yes | Codetext | m² | Trockenbauarbeiten | Wand | Außenwand 7-Schalig | WA-LB | 0 | A | 11.25 | 1255HWa0000000073 | NEW | no | yes | 0 | 0 | no | 0 | no | Codetext
 | H2 Ebene +3 | WA-DL | 1255Wa 0811569074 | yes | Codetext | m³ | Zimmer- und Holzbauarbeiten | Wand | Außenwand 7-Schalig | WA-DL | 0 | A | 11.25 | 1255HWa0000000073 | NEW | no | yes | 0 | 0 | no | 0 | no | Codetext | AllplanAttributes - ash D_Detailverweis: DT D; ash D_Plannummer: D1851
 | H2 Ebene +3 | WA-DL | 1255Wa 0811569075 | yes | Codetext | m³ | Zimmer- und Holzbauarbeiten | Wand | Außenwand 7-Schalig | WA-DL | 0 | A | 11.25 | 1255HWa0000000073 | NEW | no | yes | 0 | 0 | no | 0 | no | Codetext
 | H2 Ebene +3 | WA-DL | 1255Wa 0811569076 | yes | Codetext | m³ | Zimmer- und Holzbauarbeiten | Wand | Außenwand 7-Schalig | WA-DL | 0 | A | 11.25 | 1255HWa0000000073 | NEW | no | yes | 0 | 0 | no | 0 | no | Codetext
 | H2 Ebene +3 | WA-LB | 1255Wa 0811569077 | yes | Codetext | m² | Trockenbauarbeiten | Wand | Außenwand 7-Schalig | WA-LB | 0 | A | 11.25 | 1255HWa0000000073 | NEW | no | yes | 0 | 0 | no | 0 | no | Codetext
 | H2 Ebene +3 | WA-KL | 1255Wa 0811569078 | yes | Codetext | m² | Zimmer- und Holzbauarbeiten | Wand | Außenwand 7-Schalig | WA-KL | 0 | A | 11.25 | 1255HWa0000000073 | NEW | no | yes | 0 | 0 | no | 0 | no | Codetext
 | H2 Ebene +3 | WA-TL | 1255Wa 0811569079 | yes | Codetext | m² | Zimmer- und Holzbauarbeiten | Wand | Außenwand 7-Schalig | WA-TL | 0 | A | 11.25 | 1255HWa0000000073 | NEW | no | yes | 0 | 0 | no | 0 | no | Codetext
 | H2 Ebene +3 | WA-HS | 1255Wa 0811569260 | yes | Codetext | m² | Zimmer- und Holzbauarbeiten | Wand | Außenwand 7-Schalig | WA-HS | 0 | A | 11.25 | 1255HWa0000000073 | NEW | no | yes | 0 | 0 | no | 0 | no | Codetext
 | H2 Ebene +3 | WA-LB | 1255Wa 0811568962 | yes | Codetext | m² | Trockenbauarbeiten | Wand | Außenwand 7-Schalig | WA-LB | 0 | A | 11.25 | 1255HWa0000000073 | NEW | no | yes | 0 | 0 | no | 0 | no | Codetext
 | H2 Ebene +3 | WA-DL | 1255Wa 0811568963 | yes | Codetext | m³ | Zimmer- und Holzbauarbeiten | Wand | Außenwand 7-Schalig | WA-DL | 0 | A | 11.25 | 1255HWa0000000073 | NEW | no | yes | 0 | 0 | no | 0 | no | Codetext | AllplanAttributes - ash D_Detailverweis: DT D; ash D_Plannummer: D1851
 | H2 Ebene +3 | WA-DL | 1255Wa 0811568964 | yes | Codetext | m³ | Zimmer- und Holzbauarbeiten | Wand | Außenwand 7-Schalig | WA-DL | 0 | A | 11.25 | 1255HWa0000000073 | NEW | no | yes | 0 | 0 | no | 0 | no | Codetext
 | H2 Ebene +3 | WA-LB | 1255Wa 0811568965 | yes | Codetext | m² | Trockenbauarbeiten | Wand | Außenwand 7-Schalig | WA-LB | 0 | A | 11.25 | 1255HWa0000000073 | NEW | no | yes | 0 | 0 | no | 0 | no | Codetext
 | H2 Ebene +3 | WA-KL | 1255Wa 0811568966 | yes | Codetext | m² | Zimmer- und Holzbauarbeiten | Wand | Außenwand 7-Schalig | WA-KL | 0 | A | 11.25 | 1255HWa0000000073 | NEW | no | yes | 0 | 0 | no | 0 | no | Codetext
 | H2 Ebene +3 | WA-TL | 1255Wa 0811568967 | yes | Codetext | m² | Zimmer- und Holzbauarbeiten | Wand | Außenwand 7-Schalig | WA-TL | 0 | A | 11.25 | 1255HWa0000000073 | NEW | no | yes | 0 | 0 | no | 0 | no | Codetext
 | H2 Ebene +3 | WA-HS | 1255Wa 0811568968 | yes | Codetext | m² | Zimmer- und Holzbauarbeiten | Wand | Außenwand 7-Schalig | WA-HS | 0 | A | 11.25 | 1255HWa0000000073 | NEW | no | yes | 0 | 0 | no | 0 | no | Codetext
 | H2 Ebene +3 | WA-LB | 1255Wa 0811568924 | yes | Codetext | m² | Trockenbauarbeiten | Wand | Außenwand 7-Schalig | WA-LB | 0 | A | 11.25 | 1255HWa0000000073 | NEW | no | yes | 0 | 0 | no | 0 | no | Codetext
 | H2 Ebene +3 | WA-DL | 1255Wa 0811568925 | yes | Codetext | m³ | Zimmer- und Holzbauarbeiten | Wand | Außenwand 7-Schalig | WA-DL | 0 | A | 11.25 | 1255HWa0000000073 | NEW | no | yes | 0 | 0 | no | 0 | no | Codetext | AllplanAttributes - ash D_Detailverweis: DT D; ash D_Plannummer: D1851
 | H2 Ebene +3 | WA-DL | 1255Wa 0811568926 | yes | Codetext | m³ | Zimmer- und Holzbauarbeiten | Wand | Außenwand 7-Schalig | WA-DL | 0 | A | 11.25 | 1255HWa0000000073 | NEW | no | yes | 0 | 0 | no | 0 | no | Codetext
 | H2 Ebene +3 | WA-LB | 1255Wa 0811568927 | yes | Codetext | m² | Trockenbauarbeiten | Wand | Außenwand 7-Schalig | WA-LB | 0 | A | 11.25 | 1255HWa0000000073 | NEW | no | yes | 0 | 0 | no | 0 | no | Codetext
 | H2 Ebene +3 | WA-KL | 1255Wa 0811568928 | yes | Codetext | m² | Zimmer- und Holzbauarbeiten | Wand | Außenwand 7-Schalig | WA-KL | 0 | A | 11.25 | 1255HWa0000000073 | NEW | no | yes | 0 | 0 | no | 0 | no | Codetext
 | H2 Ebene +3 | WA-TL | 1255Wa 0811568929 | yes | Codetext | m² | Zimmer- und Holzbauarbeiten | Wand | Außenwand 7-Schalig | WA-TL | 0 | A | 11.25 | 1255HWa0000000073 | NEW | no | yes | 0 | 0 | no | 0 | no | Codetext
 | H2 Ebene +3 | WA-HS | 1255Wa 0811568930 | yes | Codetext | m² | Zimmer- und Holzbauarbeiten | Wand | Außenwand 7-Schalig | WA-HS | 0 | A | 11.25 | 1255HWa0000000073 | NEW | no | yes | 0 | 0 | no | 0 | no | Codetext
 | H2 Ebene +3 | WA-LB | 1255Wa 0811592253 | yes | Codetext | m² | Trockenbauarbeiten | Wand | Außenwand 7-Schalig | WA-LB | 0 | A | 11.25 | 1255HWa0000000073 | NEW | no | yes | 0 | 0 | no | 0 | no | Codetext
 | H2 Ebene +3 | WA-DL | 1255Wa 0811592254 | yes | Codetext | m³ | Zimmer- und Holzbauarbeiten | Wand | Außenwand 7-Schalig | WA-DL | 0 | A | 11.25 | 1255HWa0000000073 | NEW | no | yes | 0 | 0 | no | 0 | no | Codetext | AllplanAttributes - ash D_Detailverweis: DT D; ash D_Plannummer: D1851
 | H2 Ebene +3 | WA-DL | 1255Wa 0811592255 | yes | Codetext | m³ | Zimmer- und Holzbauarbeiten | Wand | Außenwand 7-Schalig | WA-DL | 0 | A | 11.25 | 1255HWa0000000073 | NEW | no | yes | 0 | 0 | no | 0 | no | Codetext
 | H2 Ebene +3 | WA-LB | 1255Wa 0811592256 | yes | Codetext | m² | Trockenbauarbeiten | Wand | Außenwand 7-Schalig | WA-LB | 0 | A | 11.25 | 1255HWa0000000073 | NEW | no | yes | 0 | 0 | no | 0 | no | Codetext
 | H2 Ebene +3 | WA-KL | 1255Wa 0811592257 | yes | Codetext | m² | Zimmer- und Holzbauarbeiten | Wand | Außenwand 7-Schalig | WA-KL | 0 | A | 11.25 | 1255HWa0000000073 | NEW | no | yes | 0 | 0 | no | 0 | no | Codetext
 | H2 Ebene +3 | WA-TL | 1255Wa 0811592258 | yes | Codetext | m² | Zimmer- und Holzbauarbeiten | Wand | Außenwand 7-Schalig | WA-TL | 0 | A | 11.25 | 1255HWa0000000073 | NEW | no | yes | 0 | 0 | no | 0 | no | Codetext
 | H2 Ebene +3 | WA-HS | 1255Wa 0811592259 | yes | Codetext | m² | Zimmer- und Holzbauarbeiten | Wand | Außenwand 7-Schalig | WA-HS | 0 | A | 11.25 | 1255HWa0000000073 | NEW | no | yes | 0 | 0 | no | 0 | no | Codetext
 | H2 Ebene +3 | WA-LB | 1255Wa 0811565985 | yes | Codetext | m² | Trockenbauarbeiten | Wand | Außenwand 7-Schalig | WA-LB | 0 | A | 11.25 | 1255HWa0000000073 | NEW | no | yes | 0 | 0 | no | 0 | no | Codetext
 | H2 Ebene +3 | WA-DL | 1255Wa 0811565986 | yes | Codetext | m³ | Zimmer- und Holzbauarbeiten | Wand | Außenwand 7-Schalig | WA-DL | 0 | A | 11.25 | 1255HWa0000000073 | NEW | no | yes | 0 | 0 | no | 0 | no | Codetext | AllplanAttributes - ash D_Detailverweis: DT D; ash D_Plannummer: D1851
 | H2 Ebene +3 | WA-DL | 1255Wa 0811565987 | yes | Codetext | m³ | Zimmer- und Holzbauarbeiten | Wand | Außenwand 7-Schalig | WA-DL | 0 | A | 11.25 | 1255HWa0000000073 | NEW | no | yes | 0 | 0 | no | 0 | no | Codetext
 | H2 Ebene +3 | WA-LB | 1255Wa 0811565988 | yes | Codetext | m² | Trockenbauarbeiten | Wand | Außenwand 7-Schalig | WA-LB | 0 | A | 11.25 | 1255HWa0000000073 | NEW | no | yes | 0 | 0 | no | 0 | no | Codetext
 | H2 Ebene +3 | WA-KL | 1255Wa 0811565989 | yes | Codetext | m² | Zimmer- und Holzbauarbeiten | Wand | Außenwand 7-Schalig | WA-KL | 0 | A | 11.25 | 1255HWa0000000073 | NEW | no | yes | 0 | 0 | no | 0 | no | Codetext
 | H2 Ebene +3 | WA-TL | 1255Wa 0811565990 | yes | Codetext | m² | Zimmer- und Holzbauarbeiten | Wand | Außenwand 7-Schalig | WA-TL | 0 | A | 11.25 | 1255HWa0000000073 | NEW | no | yes | 0 | 0 | no | 0 | no | Codetext
 | H2 Ebene +3 | WA-HS | 1255Wa 0811565991 | yes | Codetext | m² | Zimmer- und Holzbauarbeiten | Wand | Außenwand 7-Schalig | WA-HS | 0 | A | 11.25 | 1255HWa0000000073 | NEW | no | yes | 0 | 0 | no | 0 | no | Codetext
2x Gipsfaserplatte | H2 Ebene +3 | WA-LB | 1255Wa 0000011698 | yes |  | m² | Trockenbauarbeiten | Wand | 2x Gipsfaserplatte | WA-LB |  |  | 11.25 | 1255HWa0000011696 | NEW | no | yes | REI 60-A1 - D,s2-d0 +A1
Holzständer + Zwischendämmung | H2 Ebene +3 | WA-HD | 1255Wa 0000011699 | yes |  | m³ | Zimmer- und Holzbauarbeiten | Wand | Holzständer + Zwischendämmung | WA-HD |  |  | 11.25 | 1255HWa0000011696 | NEW | no | yes | REI 60-A1 - D,s2-d0 +A1 | AllplanAttributes - ash D_Detailverweis: DT D; ash D_Plannummer: D1851
Staffel + Zwischendämmung | H2 Ebene +3 | WA-DL | 1255Wa 0000011700 | yes |  | m³ | Zimmer- und Holzbauarbeiten | Wand | Staffel + Zwischendämmung | WA-DL |  |  | 11.25 | 1255HWa0000011696 | NEW | no | yes | REI 60-A1 - D,s2-d0 +A1
 | H2 Ebene +3 | WA-LB | 1255Wa 0000011701 | yes | Codetext | m² | Trockenbauarbeiten | Wand | Außenwand 7-Schalig | WA-LB | 0 | A | 11.25 | 1255HWa0000011696 | NEW | no | yes | 0 | 0 | no | 0 | no | Codetext
Konterlattung | H2 Ebene +3 | WA-KL | 1255Wa 0000011702 | yes |  | m² | Zimmer- und Holzbauarbeiten | Wand | Konterlattung | WA-KL |  |  | 11.25 | 1255HWa0000011696 | NEW | no | yes | REI 60-A1 - D,s2-d0 +A1
Traglattung | H2 Ebene +3 | WA-TL | 1255Wa 0000011703 | yes |  | m² | Zimmer- und Holzbauarbeiten | Wand | Traglattung | WA-TL |  |  | 11.25 | 1255HWa0000011696 | NEW | no | yes | REI 60-A1 - D,s2-d0 +A1
Holzschindel | H2 Ebene +3 | WA-HS | 1255Wa 0000011704 | yes |  | m² | Zimmer- und Holzbauarbeiten | Wand | Holzschindel | WA-HS |  |  | 11.25 | 1255HWa0000011696 | NEW | no | yes | REI 60-A1 - D,s2-d0 +A1
 | H2 Ebene +3 | WA-FAS | 1255Wa 0811497282 | yes | Codetext | m² | Vorgehängte Fassaden | Wand | Außenwand mehrschalig | WA-FAS | 0 | A |  | 1106HWa0000000475 | NEW | no | yes | 0 | 0 | no | 0 | no | Codetext
 | H2 Ebene +3 | WA-FAS | 1255Wa 0811497281 | yes | Codetext | m² | Vorgehängte Fassaden | Wand | Außenwand mehrschalig | WA-FAS | 0 | A |  | 1106HWa0000000475 | NEW | no | yes | 0 | 0 | no | 0 | no | Codetext
 | H2 Ebene +3 | WA-FAS | 1255Wa 0811498470 | yes | Codetext | m² | Vorgehängte Fassaden | Wand | Außenwand mehrschalig | WA-FAS | 0 | A |  | 1106HWa0000000475 | NEW | no | yes | 0 | 0 | no | 0 | no | Codetext
 | H2 Ebene +3 | WA-FAS | 1255Wa 0811498469 | yes | Codetext | m² | Vorgehängte Fassaden | Wand | Außenwand mehrschalig | WA-FAS | 0 | A |  | 1106HWa0000000475 | NEW | no | yes | 0 | 0 | no | 0 | no | Codetext
 | H2 Ebene +3 | WA-FAS | 1255Wa 0811495553 | yes | Codetext | m² | Vorgehängte Fassaden | Wand | Außenwand mehrschalig | WA-FAS | 0 | A |  | 1106HWa0000000475 | NEW | no | yes | 0 | 0 | no | 0 | no | Codetext
 | H2 Ebene +3 | WA-FAS | 1255Wa 0811495549 | yes | Codetext | m² | Vorgehängte Fassaden | Wand | Außenwand mehrschalig | WA-FAS | 0 | A |  | 1106HWa0000000475 | NEW | no | yes | 0 | 0 | no | 0 | no | Codetext
 | H2 Ebene +3 | WI-SYS | 1255Wa 0811495545 | yes | Codetext | m² | Trockenbauarbeiten | Wand | Außenwand mehrschalig | WI-SYS | 0 | A |  |  | NEW | no | yes | 0 | 0 | no | 0 | no | Codetext
 | H2 Ebene +3 | WI-SYS | 1255Wa 0811495541 | yes | Codetext | m² | Trockenbauarbeiten | Wand | Außenwand mehrschalig | WI-SYS | 0 | A |  |  | NEW | no | yes | 0 | 0 | no | 0 | no | Codetext
 | H2 Ebene +3 | WA-FAS | 1255Wa 0811495537 | yes | Codetext | m² | Vorgehängte Fassaden | Wand | Außenwand mehrschalig | WA-FAS | 0 | A |  | 1106HWa0000000475 | NEW | no | yes | 0 | 0 | no | 0 | no | Codetext
 | H2 Ebene +3 | WA-FAS | 1255Wa 0811495533 | yes | Codetext | m² | Vorgehängte Fassaden | Wand | Außenwand mehrschalig | WA-FAS | 0 | A |  | 1106HWa0000000475 | NEW | no | yes | 0 | 0 | no | 0 | no | Codetext
 | H2 Ebene +3 | WA-FAS | 1255Wa 0811498471 | yes | Codetext | m² | Vorgehängte Fassaden | Wand | Außenwand mehrschalig | WA-FAS | 0 | A |  | 1106HWa0000000475 | NEW | no | yes | 0 | 0 | no | 0 | no | Codetext
 | H2 Ebene +3 | WA-FAS | 1255Wa 0811498472 | yes | Codetext | m² | Vorgehängte Fassaden | Wand | Außenwand mehrschalig | WA-FAS | 0 | A |  | 1106HWa0000000475 | NEW | no | yes | 0 | 0 | no | 0 | no | Codetext
 | H2 Ebene +3 | WI-SYS | 1255Wa 0811498473 | yes | Codetext | m² | Trockenbauarbeiten | Wand | Außenwand mehrschalig | WI-SYS | 0 | A |  |  | NEW | no | yes | 0 | 0 | no | 0 | no | Codetext
 | H2 Ebene +3 | WI-SYS | 1255Wa 0811498459 | yes | Codetext | m² | Trockenbauarbeiten | Wand | Außenwand mehrschalig | WI-SYS | 0 | A |  |  | NEW | no | yes | 0 | 0 | no | 0 | no | Codetext
 | H2 Ebene +3 | WA-FAS | 1255Wa 0811498460 | yes | Codetext | m² | Vorgehängte Fassaden | Wand | Außenwand mehrschalig | WA-FAS | 0 | A |  | 1106HWa0000000475 | NEW | no | yes | 0 | 0 | no | 0 | no | Codetext
 | H2 Ebene +3 | WA-FAS | 1255Wa 0811498461 | yes | Codetext | m² | Vorgehängte Fassaden | Wand | Außenwand mehrschalig | WA-FAS | 0 | A |  | 1106HWa0000000475 | NEW | no | yes | 0 | 0 | no | 0 | no | Codetext
 | H2 Ebene +3 | ZBL | 1255Wa 0811555615 | yes |  | m | Dachabdichtungsarbeiten | Attikablech |  | ZBL |  |  |  |  | NEW | no | yes | AllplanAttributes - Attributset-Objekt: Covering
 | H2 Ebene +3 | ZBL | 1255Wa 0811558187 | yes |  | m | Dachabdichtungsarbeiten | Attikablech |  | ZBL |  |  |  |  | NEW | no | yes | AllplanAttributes - Attributset-Objekt: Covering
 | H2 Ebene +3 | ZBL | 1255Wa 0811568816 | yes |  | m | Dachabdichtungsarbeiten | Attikablech |  | ZBL |  |  |  |  | NEW | no | yes | AllplanAttributes - Attributset-Objekt: Covering
 | H2 Ebene +3 | ZBL | 1255Wa 0811568813 | yes |  | m | Dachabdichtungsarbeiten | Attikablech |  | ZBL |  |  |  |  | NEW | no | yes | AllplanAttributes - Attributset-Objekt: Covering
 | H2 Ebene +3 | WA-LB | 1255Wa 0811561924 | yes | Codetext | m² | Trockenbauarbeiten | Wand | Außenwand 7-Schalig | WA-LB | 0 | A | 11.25 | 1255HWa0000000073 | NEW | no | yes | 0 | 0 | no | 0 | no | Codetext
 | H2 Ebene +3 | WA-DL | 1255Wa 0811561925 | yes | Codetext | m³ | Zimmer- und Holzbauarbeiten | Wand | Außenwand 7-Schalig | WA-DL | 0 | A | 11.25 | 1255HWa0000000073 | NEW | no | yes | 0 | 0 | no | 0 | no | Codetext | AllplanAttributes - ash D_Detailverweis: DT D; ash D_Plannummer: D1851
 | H2 Ebene +3 | WA-DL | 1255Wa 0811561926 | yes | Codetext | m³ | Zimmer- und Holzbauarbeiten | Wand | Außenwand 7-Schalig | WA-DL | 0 | A | 11.25 | 1255HWa0000000073 | NEW | no | yes | 0 | 0 | no | 0 | no | Codetext
 | H2 Ebene +3 | WA-LB | 1255Wa 0811561927 | yes | Codetext | m² | Trockenbauarbeiten | Wand | Außenwand 7-Schalig | WA-LB | 0 | A | 11.25 | 1255HWa0000000073 | NEW | no | yes | 0 | 0 | no | 0 | no | Codetext
 | H2 Ebene +3 | WA-KL | 1255Wa 0811561928 | yes | Codetext | m² | Zimmer- und Holzbauarbeiten | Wand | Außenwand 7-Schalig | WA-KL | 0 | A | 11.25 | 1255HWa0000000073 | NEW | no | yes | 0 | 0 | no | 0 | no | Codetext
 | H2 Ebene +3 | WA-TL | 1255Wa 0811561929 | yes | Codetext | m² | Zimmer- und Holzbauarbeiten | Wand | Außenwand 7-Schalig | WA-TL | 0 | A | 11.25 | 1255HWa0000000073 | NEW | no | yes | 0 | 0 | no | 0 | no | Codetext
 | H2 Ebene +3 | WA-HS | 1255Wa 0811561930 | yes | Codetext | m² | Zimmer- und Holzbauarbeiten | Wand | Außenwand 7-Schalig | WA-HS | 0 | A | 11.25 | 1255HWa0000000073 | NEW | no | yes | 0 | 0 | no | 0 | no | Codetext
 | H2 Ebene +3 | WI-WC | 1263Wa 0812772213 | yes | Codetext | m² | Tischlerarbeiten | Wand | WC Trennwand | WI-WC | 0 | A | 11.25 | 1263HWa0812772197 | NEW |  | no | 0 | 0 | no | 0 | no | Codetext
 | H2 Ebene +3 | WI-WC | 1263Wa 0812772214 | yes | Codetext | m² | Tischlerarbeiten | Wand | WC Trennwand | WI-WC | 0 | A | 11.25 | 1263HWa0812772199 | NEW |  | no | 0 | 0 | no | 0 | no | Codetext
 | H2 Ebene +3 | WI-WC | 1263Wa 0812772215 | yes | Codetext | m² | Tischlerarbeiten | Wand | WC Trennwand | WI-WC | 0 | A | 11.25 | 1263HWa0812772201 | NEW |  | no | 0 | 0 | no | 0 | no | Codetext
 | H2 Ebene +3 | WI-WC | 1263Wa 0812772216 | yes | Codetext | m² | Tischlerarbeiten | Wand | WC Trennwand | WI-WC | 0 | A | 11.25 | 1263HWa0812772203 | NEW |  | no | 0 | 0 | no | 0 | no | Codetext
 | H2 Ebene +3 | WI-WC | 1263Wa 0812772212 | yes | Codetext | m² | Tischlerarbeiten | Wand | WC Trennwand | WI-WC | 0 | A | 11.25 | 1263HWa0812772205 | NEW |  | no | 0 | 0 | no | 0 | no | Codetext
 | H2 Ebene +3 | WI-WC | 1263Wa 0812772221 | yes | Codetext | m² | Tischlerarbeiten | Wand | WC Trennwand | WI-WC | 0 | A | 11.25 | 1263HWa0812772184 | NEW |  | no | 0 | 0 | no | 0 | no | Codetext
 | H2 Ebene +3 | WI-WC | 1263Wa 0812771578 | yes | Codetext | m² | Tischlerarbeiten | Wand | WC Trennwand | WI-WC | 0 | A | 11.25 | 1263HWa0812771576 | NEW |  | no | 0 | 0 | no | 0 | no | Codetext
 | H2 Ebene +3 | WI-WC | 1263Wa 0812771571 | yes | Codetext | m² | Tischlerarbeiten | Wand | WC Trennwand | WI-WC | 0 | A | 11.25 | 1263HWa0812771569 | NEW |  | no | 0 | 0 | no | 0 | no | Codetext
 | H2 Ebene +3 | WI-WC | 1263Wa 0812771548 | yes | Codetext | m² | Tischlerarbeiten | Wand | WC Trennwand | WI-WC | 0 | A | 11.25 | 1263HWa0812771547 | NEW |  | no | 0 | 0 | no | 0 | no | Codetext
 | H2 Ebene +3 | WI-WC | 1263Wa 0812771563 | yes | Codetext | m² | Tischlerarbeiten | Wand | WC Trennwand | WI-WC | 0 | A | 11.25 | 1263HWa0812771562 | NEW |  | no | 0 | 0 | no | 0 | no | Codetext
 | H2 Ebene +3 | WI-WC | 1263Wa 0812771585 | yes | Codetext | m² | Tischlerarbeiten | Wand | WC Trennwand | WI-WC | 0 | A | 11.25 | 1263HWa0812771583 | NEW | no | no | 0 | 0 | no | 0 | no | Codetext
 | H2 Ebene +3 | WI-WC | 1263Wa 0812769623 | yes | Codetext | m² | Tischlerarbeiten | Wand | WC Trennwand | WI-WC | 0 | A | 11.25 | 1263HWa0812769622 | NEW | no | no | 0 | 0 | no | 0 | no | Codetext
 | H2 Ebene +3 | WI-LB | 1263Wa 0812845779 | yes | Codetext | m² | Trockenbauarbeiten | Wand | Innenwand 1-Schalig | WI-LB | 0 | A | 11.25 | 1263HWa0812845778 | NEW |  | no | REI 60-A1 - D,s2-d0 +A1 | 0 | no | 0 | no | Codetext
 | H2 Ebene +3 | WI-LB | 1263Wa 0812546881 | yes | Codetext | m² | Trockenbauarbeiten | Wand | Innenwand 1-Schalig | WI-LB | 0 | A | 11.25 | 1263HWa0812546497 | NEW | no | no | REI-M 60-A1 | 0 | no | 47 | no | Codetext | AllplanAttributes - Ortscode_Geschoßbezeichnung: E03; W_Deckenanschluss: Gleitender Deckenanschluss Fall 01; ash_W_Trockenbau_Qualitäten: 1b
 | H2 Ebene +3 | WI-LB | 1263Wa 0812750839 | yes | Codetext | m² | Trockenbauarbeiten | Wand |  | WI-LB | 0 | A | 11.25 | 1263HWa0812750837 | NEW | no | no | REI 60-A1 - A2,s1-d0 / A1 | 0 | no | 0 | no | Codetext
 | H2 Ebene +3 | WI-LB | 1263Wa 0812750827 | yes | Codetext | m² | Trockenbauarbeiten | Wand |  | WI-LB | 0 | A | 11.25 | 1263HWa0812750825 | NEW | no | no | REI 60-A1 - A2,s1-d0 / A1 | 0 | no | 0 | no | Codetext
 | H2 Ebene +3 | WI-LB | 1263Wa 0812750834 | yes | Codetext | m² | Trockenbauarbeiten | Wand |  | WI-LB | 0 | A | 11.25 | 1263HWa0812750832 | NEW | no | no | REI 60-A1 - A2,s1-d0 / A1 | 0 | no | 0 | no | Codetext
 | H2 Ebene +3 | WI-LB | 1263Wa 0812750822 | yes | Codetext | m² | Trockenbauarbeiten | Wand |  | WI-LB | 0 | A | 11.25 | 1263HWa0812750820 | NEW | no | no | REI 60-A1 - A2,s1-d0 / A1 | 0 | no | 0 | no | Codetext
 | H2 Ebene +3 | WI-LW 60 | 1263Wa 0812939719 | yes | Codetext | m² | Trockenbauarbeiten | Wand | Innenwand 1-Schalig | WI-LW 60 | 0 | A | 11.25 | 1263HWa0812547005 | NEW | yes | no | REI-M 60-D,s2,d0 + A1 | 0 | no | 0 | no | Codetext | AllplanAttributes - ash_W_Trockenbau_Qualitäten: 12a
 | H2 Ebene +3 | WI-LB | 1263Wa 0812982124 | yes | Codetext | m² | Trockenbauarbeiten | Wand | Innenwand 1-Schalig | WI-LB | 0 | A | 11.25 | 1263HWa0812544980 | NEW |  | no | REI 60-A1 - D,s2-d0 +A1 | 0 | no | 0 | no | Codetext | AllplanAttributes - ash_W_Trockenbau_Qualitäten: 9
 | H2 Ebene +3 | WI-LB | 1263Wa 0812982470 | yes | Codetext | m² | Trockenbauarbeiten | Wand | Innenwand 1-Schalig | WI-LB | 0 | A | 11.25 | 1263HWa0812544980 | NEW |  | no | REI 60-A1 - D,s2-d0 +A1 | 0 | no | 0 | no | Codetext | AllplanAttributes - ash_W_Trockenbau_Qualitäten: 9
 | H2 Ebene +3 | WI-LB | 1263Wa 0812982652 | yes | Codetext | m² | Trockenbauarbeiten | Wand | Innenwand 1-Schalig | WI-LB | 0 | A | 11.25 | 1263HWa0812544980 | NEW |  | no | REI 60-A1 - D,s2-d0 +A1 | 0 | no | 0 | no | Codetext | AllplanAttributes - ash_W_Trockenbau_Qualitäten: 9
 | H2 Ebene +3 | WI-LB | 1263Wa 0812982795 | yes | Codetext | m² | Trockenbauarbeiten | Wand | Innenwand 1-Schalig | WI-LB | 0 | A | 11.25 | 1263HWa0812544980 | NEW |  | no | REI 60-A1 - D,s2-d0 +A1 | 0 | no | 0 | no | Codetext | AllplanAttributes - ash_W_Trockenbau_Qualitäten: 9
 | H2 Ebene +3 | WI-STB | 1263Wa 0812546918 | yes | Codetext | m² | Betonarbeiten | Wand | Innenwand 1-Schalig | WI-STB | 0 | A | 11.25 | 1263HWa0812545276 | NEW | yes | no | REI 60-A1 - A2,s1-d0 / A1 | 0 | no | 0 | yes | Codetext | AllplanAttributes - Ortscode_Geschoßbezeichnung: E03
 | H2 Ebene +3 | WI-STB | 1263Wa 0812989898 | yes | Codetext | m² | Betonarbeiten | Wand | Innenwand 1-Schalig | WI-STB | 0 | A | 11.25 | 1263HWa0812545276 | NEW | yes | no | REI 60-A1 - A2,s1-d0 / A1 | 0 | no | 42 | yes | Codetext | AllplanAttributes - Ortscode_Geschoßbezeichnung: E03
 | H2 Ebene +3 | WI-HW 60 | 1263Wa 0812602160 | yes | Codetext | m² | Trockenbauarbeiten | Wand | Innenwand 1-Schalig | WI-HW 60 | 0 | A | 11.25 | 1263HWa0812602159 | NEW | yes | no | REI-M 60-D,s2,d0 + A1 | 0 | no | 0 | no | Codetext | AllplanAttributes - ash D_Detailverweis: DT 7; ash D_Plannummer: D1613
 | H2 Ebene +3 | WA-STB | 1263Wa 0812546097 | yes | Codetext | m² | Betonarbeiten | Wand | Innenwand 1-Schalig | WA-STB | 0 | A | 11.25 | 1263HWa0812545465 | NEW | yes | no | REI-M 60-A1 | 0 | no | 0 | no | Codetext | AllplanAttributes - ash D_Detailverweis: DT 6; ash D_Plannummer: D1613; Text1: SB3
 | H2 Ebene +3 | WI-STB | 1263Wa 0812546945 | yes | Codetext | m² | Betonarbeiten | Wand | Innenwand 1-Schalig | WI-STB | 0 | A | 11.25 | 1263HWa0812545467 | NEW | yes | no | REI-M 60-A1 | 0 | no | 0 | no | Codetext | AllplanAttributes - ash D_Detailverweis: DT 5; ash D_Plannummer: D1614; Text1: SB3
 | H2 Ebene +3 | WI-LB | 1263Wa 0812546867 | yes | Codetext | m² | Trockenbauarbeiten | Wand | Innenwand 1-Schalig | WI-LB | 0 | A | 11.25 | 1263HWa0812544238 | NEW | no | no | REI 60-A1 - D,s2-d0 +A1 | 0 | no | 0 | no | Codetext | AllplanAttributes - ash_W_Trockenbau_Qualitäten: 9
 | H2 Ebene +3 | WI-STB | 1263Wa 0812982187 | yes | Codetext | m² | Betonarbeiten | Wand | Innenwand 1-Schalig | WI-STB | 0 | A | 11.25 | 1263HWa0812544238 | NEW | yes | no | REI 60-A1 - A2,s1-d0 / A1 | 0 | no | 0 | no | Codetext | AllplanAttributes - ash D_Detailverweis: DT 3; ash D_Plannummer: D1615; Text1: SB3
 | H2 Ebene +3 | WI-STB | 1263Wa 0812546848 | yes | Codetext | m² | Betonarbeiten | Wand | Innenwand 1-Schalig | WI-STB | 0 | A | 11.25 | 1263HWa0812544239 | NEW | yes | no | REI-M 60-A1 | 0 | no | 0 | no | Codetext | AllplanAttributes - ash D_Detailverweis: DT 3; ash D_Plannummer: D1615; Text1: SB3
 | H2 Ebene +3 | WI-STB | 1263Wa 0812610108 | yes | Codetext | m² | Betonarbeiten | Wand | Innenwand 1-Schalig | WI-STB | 0 | A | 11.25 | 1263HWa0812610107 | NEW | yes | no | REI 60-A1 - A2,s1-d0 / A1 | 0 | no | 0 | no | Codetext | AllplanAttributes - ash D_Detailverweis: DT 3; ash D_Plannummer: D1615
 | H2 Ebene +3 | WI-LB | 1263Wa 0812546820 | yes | Codetext | m² | Trockenbauarbeiten | Wand | Innenwand 1-Schalig | WI-LB | 0 | A | 11.25 | 1263HWa0812546813 | NEW | no | no | REI 60-A1 - A2,s1-d0 / A1 | 0 | no | 0 | no | Codetext | AllplanAttributes - W_Deckenanschluss: Gleitender Deckenanschluss Fall 01
 | H2 Ebene +3 | WI-LB | 1263Wa 0812546818 | yes | Codetext | m² | Trockenbauarbeiten | Wand | Innenwand 1-Schalig | WI-LB | 0 | A | 11.25 | 1263HWa0812545245 | NEW | no | no | REI 60-A1 - A2,s1-d0 / A1 | 0 | no | 0 | no | Codetext | AllplanAttributes - W_Deckenanschluss: Gleitender Deckenanschluss Fall 01; ash_W_Trockenbau_Qualitäten: 1b
 | H2 Ebene +3 | WI-HW 60 | 1263Wa 0812597389 | yes | Codetext | m² | Trockenbauarbeiten | Wand | Innenwand 1-Schalig | WI-HW 60 | 0 | A | 11.25 | 1263HWa0812597388 | NEW | yes | no | 0 | 0 | no | 0 | no | Codetext
 | H2 Ebene +3 | WI-LB | 1263Wa 0812546119 | yes | Codetext | m² | Trockenbauarbeiten | Wand | Innenwand 1-Schalig | WI-LB | 0 | A | 11.25 | 1263HWa0812545395 | NEW | no | no | REI 60-A1 - A2,s1-d0 / A1 | 0 | no | 0 | no | Codetext | AllplanAttributes - W_Deckenanschluss: Gleitender Deckenanschluss Fall 01; ash_W_Trockenbau_Qualitäten: 1b
 | H2 Ebene +3 | WI-LB | 1263Wa 0812546968 | yes | Codetext | m² | Trockenbauarbeiten | Wand | Innenwand 1-Schalig | WI-LB | 0 | A | 11.25 | 1263HWa0812545191 | NEW | no | no | REI 60-A1 - A2,s1-d0 / A1 | 0 | no | 0 | no | Codetext | AllplanAttributes - W_Deckenanschluss: Gleitender Deckenanschluss Fall 01; ash_W_Trockenbau_Qualitäten: 1b
 | H2 Ebene +3 | WI-LB | 1263Wa 0812995088 | yes | Codetext | m² | Trockenbauarbeiten | Wand | Innenwand 1-Schalig | WI-LB | 0 | A | 11.25 | 1263HWa0812545245 | NEW | no | no | REI 60-A1 - A2,s1-d0 / A1 | 0 | no | 0 | no | Codetext | AllplanAttributes - W_Deckenanschluss: Gleitender Deckenanschluss Fall 01; ash_W_Trockenbau_Qualitäten: 1b
 | H2 Ebene +3 | WI-LB | 1263Wa 0812996302 | yes | Codetext | m² | Trockenbauarbeiten | Wand | Innenwand 1-Schalig | WI-LB | 0 | A | 11.25 | 1263HWa0812545395 | NEW | no | no | REI 60-A1 - A2,s1-d0 / A1 | 0 | no | 0 | no | Codetext | AllplanAttributes - W_Deckenanschluss: Gleitender Deckenanschluss Fall 01; ash_W_Trockenbau_Qualitäten: 1b
 | H2 Ebene +3 | WI-LB | 1263Wa 0812547467 | yes | Codetext | m² | Trockenbauarbeiten | Wand | Innenwand 1-Schalig | WI-LB | 0 | A | 11.25 | 1263HWa0812544127 | NEW | no | no | REI 60-A1 - A2,s1-d0 / A1 | 0 | no | 0 | no | Codetext | AllplanAttributes - W_Deckenanschluss: Gleitender Deckenanschluss Fall 01; ash_W_Trockenbau_Qualitäten: 1b
 | H2 Ebene +3 | WI-LB | 1263Wa 0812546514 | yes | Codetext | m² | Trockenbauarbeiten | Wand | Innenwand 1-Schalig | WI-LB | 0 | A | 11.25 | 1263HWa0812545216 | NEW | no | no | REI 60-A1 - A2,s1-d0 / A1 | 0 | no | 0 | no | Codetext | AllplanAttributes - W_Deckenanschluss: Gleitender Deckenanschluss Fall 01; ash_W_Trockenbau_Qualitäten: 1b
 | H2 Ebene +3 | WI-LB | 1263Wa 0812730978 | yes | Codetext | m² | Trockenbauarbeiten | Wand | Innenwand 1-Schalig | WI-LB | 0 | A | 11.25 | 1263HWa0812730977 | NEW | no | no | REI 60-A1 - A2,s1-d0 / A1 | 0 | no | 0 | no | Codetext | AllplanAttributes - W_Deckenanschluss: Gleitender Deckenanschluss Fall 01; ash_W_Trockenbau_Qualitäten: 1b
 | H2 Ebene +3 | WI-LB | 1263Wa 0812546518 | yes | Codetext | m² | Trockenbauarbeiten | Wand | Innenwand 1-Schalig | WI-LB | 0 | A | 11.25 | 1263HWa0812544221 | NEW | no | no | REI 60-A1 - A2,s1-d0 / A1 | 0 | no | 0 | no | Codetext | AllplanAttributes - W_Deckenanschluss: Gleitender Deckenanschluss Fall 01; ash_W_Trockenbau_Qualitäten: 1b
 | H2 Ebene +3 | WI-HW 60 | 1263Wa 0812547473 | yes | Codetext | m² | Trockenbauarbeiten | Wand | Innenwand 1-Schalig | WI-HW 60 | 0 | A | 11.25 | 1263HWa0812546525 | NEW | no | no | REI-M 60-D,s2,d0 + A1 | 0 | no | 0 | no | Codetext | AllplanAttributes - ash D_Detailverweis: DT 8; ash D_Plannummer: D1613
 | H2 Ebene +3 | WI-HW 60 | 1263Wa 0812547464 | yes | Codetext | m² | Trockenbauarbeiten | Wand | Innenwand 1-Schalig | WI-HW 60 | 0 | A | 11.25 | 1263HWa0812546507 | NEW | no | no | REI-M 60-D,s2,d0 + A1 | 0 | no | 0 | no | Codetext | AllplanAttributes - ash D_Detailverweis: DT 7; ash D_Plannummer: D1613
 | H2 Ebene +3 | WI-HW 60 | 1263Wa 0812547469 | yes | Codetext | m² | Trockenbauarbeiten | Wand | Innenwand 1-Schalig | WI-HW 60 | 0 | A | 11.25 | 1263HWa0812546505 | NEW | no | no | REI-M 60-D,s2,d0 + A1 | 0 | no | 0 | no | Codetext
 | H2 Ebene +3 | WI-LW 60 | 1263Wa 0812546695 | yes | Codetext | m² | Trockenbauarbeiten | Wand | Innenwand 1-Schalig | WI-LW 60 | 0 | A | 11.25 | 1263HWa0812546608 | NEW | no | no | REI-M 60-D,s2,d0 + A1 | 0 | no | 0 | no | Codetext | AllplanAttributes - ash_W_Trockenbau_Qualitäten: 12a
 | H2 Ebene +3 | WI-HW 60 | 1263Wa 0812546692 | yes | Codetext | m² | Trockenbauarbeiten | Wand | Innenwand 1-Schalig | WI-HW 60 | 0 | A | 11.25 | 1263HWa0812546596 | NEW | no | no | REI-M 60-D,s2,d0 + A1 | 0 | no | 0 | no | Codetext | AllplanAttributes - ash D_Detailverweis: DT 8; ash D_Plannummer: D1613
 | H2 Ebene +3 | WI-LB | 1263Wa 0812976171 | yes | Codetext | m² | Trockenbauarbeiten | Wand | Innenwand 1-Schalig | WI-LB | 0 | A | 11.25 | 1263HWa0812545193 | NEW | no | no | REI 60-A1 - D,s2-d0 +A1 | 0 | no | 0 | no | Codetext | AllplanAttributes - W_Deckenanschluss: Gleitender Deckenanschluss Fall 01; ash_W_Trockenbau_Qualitäten: 1b
 | H2 Ebene +3 | WI-LB | 1263Wa 0812546964 | yes | Codetext | m² | Trockenbauarbeiten | Wand | Innenwand 1-Schalig | WI-LB | 0 | A | 11.25 | 1263HWa0812544128 | NEW | no | no | REI 60-A1 - A2,s1-d0 / A1 | 0 | no | 0 | no | Codetext | AllplanAttributes - W_Deckenanschluss: Gleitender Deckenanschluss Fall 01; ash_W_Trockenbau_Qualitäten: 1b
 | H2 Ebene +3 | WI-LB | 1263Wa 0812546978 | yes | Codetext | m² | Trockenbauarbeiten | Wand | Innenwand 1-Schalig | WI-LB | 0 | A | 11.25 | 1263HWa0812544126 | NEW | no | no | REI 60-A1 - A2,s1-d0 / A1 | 0 | no | 0 | no | Codetext | AllplanAttributes - W_Deckenanschluss: Gleitender Deckenanschluss Fall 01; ash_W_Trockenbau_Qualitäten: 1b
 | H2 Ebene +3 | WI-LB | 1263Wa 0812546987 | yes | Codetext | m² | Trockenbauarbeiten | Wand | Innenwand 1-Schalig | WI-LB | 0 | A | 11.25 | 1263HWa0812544103 | NEW | no | no | REI 60-A1 - A2,s1-d0 / A1 | 0 | no | 0 | no | Codetext | AllplanAttributes - W_Deckenanschluss: Gleitender Deckenanschluss Fall 01; ash_W_Trockenbau_Qualitäten: 1b
 | H2 Ebene +3 | WI-LB | 1263Wa 0812546954 | yes | Codetext | m² | Trockenbauarbeiten | Wand | Innenwand 1-Schalig | WI-LB | 0 | A | 11.25 | 1263HWa0812545194 | NEW | no | no | REI 60-A1 - A2,s1-d0 / A1 | 0 | no | 0 | no | Codetext | AllplanAttributes - W_Deckenanschluss: Gleitender Deckenanschluss Fall 01; ash_W_Trockenbau_Qualitäten: 1b
 | H2 Ebene +3 | WI-LB | 1263Wa 0812975466 | yes | Codetext | m² | Trockenbauarbeiten | Wand | Innenwand 1-Schalig | WI-LB | 0 | A | 11.25 | 1263HWa0812545193 | NEW | no | no | REI 60-A1 - D,s2-d0 +A1 | 0 | no | 0 | no | Codetext | AllplanAttributes - W_Deckenanschluss: Gleitender Deckenanschluss Fall 01; ash_W_Trockenbau_Qualitäten: 1b
 | H2 Ebene +3 | WI-LB | 1263Wa 0812975471 | yes | Codetext | m² | Trockenbauarbeiten | Wand | Innenwand 1-Schalig | WI-LB | 0 | A | 11.25 | 1263HWa0812545193 | NEW | no | no | REI 60-A1 - D,s2-d0 +A1 | 0 | no | 0 | no | Codetext | AllplanAttributes - W_Deckenanschluss: Gleitender Deckenanschluss Fall 01; ash_W_Trockenbau_Qualitäten: 1a
 | H2 Ebene +3 | WI-LB | 1263Wa 0812546950 | yes | Codetext | m² | Trockenbauarbeiten | Wand | Innenwand 1-Schalig | WI-LB | 0 | A | 11.25 | 1263HWa0812545193 | NEW | no | no | REI 60-A1 - D,s2-d0 +A1 | 0 | no | 0 | no | Codetext | AllplanAttributes - W_Deckenanschluss: Gleitender Deckenanschluss Fall 01; ash_W_Trockenbau_Qualitäten: 1b
 | H2 Ebene +3 | WI-HW 60 | 1263Wa 0812546725 | yes | Codetext | m² | Trockenbauarbeiten | Wand | Innenwand 1-Schalig | WI-HW 60 | 0 | A | 11.25 | 1263HWa0812544344 | NEW | no | no | REI-M 60-D,s2,d0 + A1 | 0 | no | 0 | no | Codetext | AllplanAttributes - ash D_Detailverweis: DT 7; ash D_Plannummer: D1614
 | H2 Ebene +3 | WI-HW 60 | 1263Wa 0812844661 | yes | Codetext | m² | Trockenbauarbeiten | Wand | Innenwand 1-Schalig | WI-HW 60 | 0 | A | 11.25 | 1263HWa0812844429 | NEW | yes | no | REI 60-A1 - A2,s1-d0 / A1 | 0 | no |  | no | Codetext | AllplanAttributes - ash D_Detailverweis: J2; ash D_Plannummer: D1651
 | H2 Ebene +3 | WI-HW 60 | 1263Wa 0812546503 | yes | Codetext | m² | Trockenbauarbeiten | Wand | Innenwand 1-Schalig | WI-HW 60 | 0 | A | 11.25 | 1263HWa0812546501 | NEW | yes | no | REI 60-A1 - A2,s1-d0 / A1 | 0 | no |  | no | Codetext
 | H2 Ebene +3 | WI-HW 60 | 1263Wa 0812915391 | yes | Codetext | m² | Trockenbauarbeiten | Wand | Innenwand 1-Schalig | WI-HW 60 | 0 | A | 11.25 | 1263HWa0812915121 | NEW | yes | no | REI 60-A1 - A2,s1-d0 / A1 | 0 | no | 47 | no | Codetext
 | H2 Ebene +3 | WI-LB | 1263Wa 0812595070 | yes | Codetext | m² | Trockenbauarbeiten | Wand | Innenwand 1-Schalig | WI-LB | 0 | A | 11.25 | 1263HWa0812595068 | NEW | no | no | REI 60-A1 - A2,s1-d0 / A1 | 0 | no | 47 | no | Codetext | AllplanAttributes - W_Deckenanschluss: Gleitender Deckenanschluss Fall 01; ash_W_Trockenbau_Qualitäten: 1b
 | H2 Ebene +3 | WI-HW 60 | 1263Wa 0812914806 | yes | Codetext | m² | Trockenbauarbeiten | Wand | Innenwand 1-Schalig | WI-HW 60 | 0 | A | 11.25 | 1263HWa0812914546 | NEW | yes | no | REI 60-A1 - A2,s1-d0 / A1 | 0 | no | 47 | no | Codetext
 | H2 Ebene +3 | WI-HW 60 | 1263Wa 0812546807 | yes | Codetext | m² | Trockenbauarbeiten | Wand | Innenwand 1-Schalig | WI-HW 60 | 0 | A | 11.25 | 1263HWa0812546799 | NEW | yes | no | REI 60-A1 - A2,s1-d0 / A1 | 0 | no | 0 | no | Codetext
 | H2 Ebene +3 | WI-LB | 1263Wa 0812595718 | yes | Codetext | m² | Trockenbauarbeiten | Wand | Innenwand 1-Schalig | WI-LB | 0 | A | 11.25 | 1263HWa0812595716 | NEW | no | no | 0 | 0 | no | 0 | no | Codetext | AllplanAttributes - W_Deckenanschluss: Gleitender Deckenanschluss Fall 01; ash_W_Trockenbau_Qualitäten: 10a
 | H2 Ebene +3 | WI-LB | 1263Wa 0812595658 | yes | Codetext | m² | Trockenbauarbeiten | Wand | Innenwand 1-Schalig | WI-LB | 0 | A | 11.25 | 1263HWa0812595656 | NEW | no | no | 0 | 0 | no | 0 | no | Codetext | AllplanAttributes - W_Deckenanschluss: Gleitender Deckenanschluss Fall 01; ash_W_Trockenbau_Qualitäten: 10a
 | H2 Ebene +3 | Installationsraum | 1263Wa 0812596023 | yes | Codetext | m² | Trockenbauarbeiten | Wand | Installationswand | Installationsraum | 0 | A | 11.25 | 1263HWa0812596018 | NEW | no | no | 0 | 0 | no | 0 | no | Codetext | AllplanAttributes - W_Deckenanschluss: Gleitender Deckenanschluss Fall 01
 | H2 Ebene +3 | WI-VS | 1263Wa 0812596025 | yes | Codetext | m² | Trockenbauarbeiten | Wand | Installationswand | WI-VS | 0 | A | 11.25 | 1263HWa0812596018 | NEW | no | no | 0 | 0 | no | 0 | no | Codetext | AllplanAttributes - W_Deckenanschluss: Gleitender Deckenanschluss Fall 01; ash_W_Trockenbau_Qualitäten: 3
 | H2 Ebene +3 | Installationsraum | 1263Wa 0812596027 | yes | Codetext | m² | Trockenbauarbeiten | Wand | Installationswand | Installationsraum | 0 | A | 11.25 | 1263HWa0812596019 | NEW | no | no | 0 | 0 | no | 0 | no | Codetext | AllplanAttributes - W_Deckenanschluss: Gleitender Deckenanschluss Fall 01
 | H2 Ebene +3 | WI-VS | 1263Wa 0812596029 | yes | Codetext | m² | Trockenbauarbeiten | Wand | Installationswand | WI-VS | 0 | A | 11.25 | 1263HWa0812596019 | NEW | no | no | 0 | 0 | no | 0 | no | Codetext | AllplanAttributes - W_Deckenanschluss: Gleitender Deckenanschluss Fall 01; ash_W_Trockenbau_Qualitäten: 3
 | H2 Ebene +3 | WI-STB | 1263Wa 0812546875 | yes | Codetext | m² | Betonarbeiten | Wand | Innenwand 1-Schalig | WI-STB | 0 | A | 11.25 | 1263HWa0812544237 | NEW | yes | no | REI-M 60-A1 | 0 | no | 0 | no | Codetext | AllplanAttributes - ash D_Detailverweis: DT 3; ash D_Plannummer: D1615; Text1: SB3
 | H2 Ebene +3 | WI-LB | 1263Wa 0812546811 | yes | Codetext | m² | Trockenbauarbeiten | Wand | Innenwand 1-Schalig | WI-LB | 0 | A | 11.25 | 1263HWa0812544238 | NEW | no | no | REI 60-A1 - D,s2-d0 +A1 | 0 | no | 0 | no | Codetext | AllplanAttributes - ash_W_Trockenbau_Qualitäten: 9
 | H2 Ebene +3 | WI-STB | 1263Wa 0812795009 | yes | Codetext | m² | Betonarbeiten | Wand | Innenwand 1-Schalig | WI-STB | 0 | A | 11.25 | 1263HWa0812544238 | NEW | yes | no | REI 60-A1 - A2,s1-d0 / A1 | 0 | no | 0 | no | Codetext | AllplanAttributes - ash D_Detailverweis: DT 3; ash D_Plannummer: D1615; Text1: SB3
 | H2 Ebene +3 | WI-STB | 1263Wa 0812609602 | yes | Codetext | m² | Betonarbeiten | Wand | Innenwand 1-Schalig | WI-STB | 0 | A | 11.25 | 1263HWa0812609490 | NEW | yes | no | REI 60-A1 - A2,s1-d0 / A1 | 0 | no | 0 | no | Codetext
 | H2 Ebene +3 | WI-LB | 1263Wa 0812794375 | yes | Codetext | m² | Trockenbauarbeiten | Wand | Innenwand 1-Schalig | WI-LB | 0 | A | 11.25 | 1263HWa0812609490 | NEW | no | no | REI 60-A1 - D,s2-d0 +A1 | 0 | no | 0 | no | Codetext | AllplanAttributes - ash_W_Trockenbau_Qualitäten: 9
 | H2 Ebene +3 | WI-HW 60 | 1263Wa 0812546332 | yes | Codetext | m² | Trockenbauarbeiten | Wand | Innenwand 1-Schalig | WI-HW 60 | 0 | A | 11.25 | 1263HWa0812545263 | NEW | yes | no | REI 60-A1 - D,s2-d0 +A1 | 0 | no | 0 | no | Codetext
 | H2 Ebene +3 | WI-LB | 1263Wa 0812546335 | yes | Codetext | m² | Trockenbauarbeiten | Wand | Innenwand 1-Schalig | WI-LB | 0 | A | 11.25 | 1263HWa0812544226 | NEW | no | no | REI 60-A1 - D,s2-d0 +A1 | 0 | no | 0 | no | Codetext | AllplanAttributes - W_Deckenanschluss: Gleitender Deckenanschluss Fall 01; ash_W_Trockenbau_Qualitäten: 12b
 | H2 Ebene +3 | WI-LB | 1263Wa 0812546410 | yes | Codetext | m² | Trockenbauarbeiten | Wand | Innenwand 1-Schalig | WI-LB | 0 | A | 11.25 | 1263HWa0812544224 | NEW | no | no | REI 60-A1 - A2,s1-d0 / A1 | 0 | no | 0 | no | Codetext | AllplanAttributes - W_Deckenanschluss: Gleitender Deckenanschluss Fall 01; ash_W_Trockenbau_Qualitäten: 1b
 | H2 Ebene +3 | WI-LB | 1263Wa 0812800515 | yes | Codetext | m² | Trockenbauarbeiten | Wand | Innenwand 1-Schalig | WI-LB | 0 | A | 11.25 | 1263HWa0812800513 | NEW | no | no | REI 60-A1 - A2,s1-d0 / A1 | 0 | no | 0 | no | Codetext | AllplanAttributes - W_Deckenanschluss: Gleitender Deckenanschluss Fall 01; ash_W_Trockenbau_Qualitäten: 1b
 | H2 Ebene +3 | WI-LB | 1263Wa 0812546916 | yes | Codetext | m² | Trockenbauarbeiten | Wand | Innenwand 1-Schalig | WI-LB | 0 | A | 11.25 | 1263HWa0812545209 | NEW | no | no | REI 60-A1 - D,s2-d0 +A1 | 0 | no | 0 | no | Codetext | AllplanAttributes - W_Deckenanschluss: Gleitender Deckenanschluss Fall 01; ash_W_Trockenbau_Qualitäten: 1b
 | H2 Ebene +3 | WI-LB | 1263Wa 0812546912 | yes | Codetext | m² | Trockenbauarbeiten | Wand | Innenwand 1-Schalig | WI-LB | 0 | A | 11.25 | 1263HWa0812545201 | NEW | no | no | REI 60-A1 - A2,s1-d0 / A1 | 0 | no | 0 | no | Codetext | AllplanAttributes - W_Deckenanschluss: Gleitender Deckenanschluss Fall 01; ash_W_Trockenbau_Qualitäten: 1b
 | H2 Ebene +3 | WI-LB | 1263Wa 0812979818 | yes | Codetext | m² | Trockenbauarbeiten | Wand | Innenwand 1-Schalig | WI-LB | 0 | A | 11.25 | 1263HWa0812843014 | NEW | no | no | REI 30 | 0 | no | 42 | no | Codetext | AllplanAttributes - W_Deckenanschluss: Gleitender Deckenanschluss Fall 01; ash_W_Trockenbau_Qualitäten: 18
 | H2 Ebene +3 | WI-LB | 1263Wa 0812979779 | yes | Codetext | m² | Trockenbauarbeiten | Wand | Innenwand 1-Schalig | WI-LB | 0 | A | 11.25 | 1263HWa0812843014 | NEW | no | no | REI 30 | 0 | no | 42 | no | Codetext | AllplanAttributes - W_Deckenanschluss: Gleitender Deckenanschluss Fall 01; ash_W_Trockenbau_Qualitäten: 18
 | H2 Ebene +3 | WI-LB | 1263Wa 0812731036 | yes | Codetext | m² | Trockenbauarbeiten | Wand | Innenwand 1-Schalig | WI-LB | 0 | A | 11.25 | 1263HWa0812731035 | NEW | no | no | REI 60-A1 - A2,s1-d0 / A1 | 0 | no | 0 | no | Codetext | AllplanAttributes - W_Deckenanschluss: Gleitender Deckenanschluss Fall 01; ash_W_Trockenbau_Qualitäten: 1b
 | H2 Ebene +3 | WI-LB | 1263Wa 0813017035 | yes | Codetext | m² | Trockenbauarbeiten | Wand | Innenwand 1-Schalig | WI-LB | 0 | A | 11.25 | 1263HWa0812731035 | NEW | no | no | REI 60-A1 - A2,s1-d0 / A1 | 0 | no | 0 | no | Codetext | AllplanAttributes - W_Deckenanschluss: Gleitender Deckenanschluss Fall 01; ash_W_Trockenbau_Qualitäten: 1b
 | H2 Ebene +3 | WI-LB | 1263Wa 0812976237 | yes | Codetext | m² | Trockenbauarbeiten | Wand | Innenwand 1-Schalig | WI-LB | 0 | A | 11.25 | 1263HWa0812545201 | NEW | no | no | REI 60-A1 - A2,s1-d0 / A1 | 0 | no | 0 | no | Codetext | AllplanAttributes - W_Deckenanschluss: Gleitender Deckenanschluss Fall 01; ash_W_Trockenbau_Qualitäten: 1b
 | H2 Ebene +3 | WI-LB | 1263Wa 0812976201 | yes | Codetext | m² | Trockenbauarbeiten | Wand | Innenwand 1-Schalig | WI-LB | 0 | A | 11.25 | 1263HWa0812545193 | NEW | no | no | REI 60-A1 - D,s2-d0 +A1 | 0 | no | 0 | no | Codetext | AllplanAttributes - W_Deckenanschluss: Gleitender Deckenanschluss Fall 01; ash_W_Trockenbau_Qualitäten: 1a
 | H2 Ebene +3 | WI-LB | 1263Wa 0812976206 | yes | Codetext | m² | Trockenbauarbeiten | Wand | Innenwand 1-Schalig | WI-LB | 0 | A | 11.25 | 1263HWa0812545201 | NEW | no | no | REI 60-A1 - A2,s1-d0 / A1 | 0 | no | 0 | no | Codetext | AllplanAttributes - W_Deckenanschluss: Gleitender Deckenanschluss Fall 01; ash_W_Trockenbau_Qualitäten: 1b
 | H2 Ebene +3 | WI-LB | 1263Wa 0812976691 | yes | Codetext | m² | Trockenbauarbeiten | Wand | Innenwand 1-Schalig | WI-LB | 0 | A | 11.25 | 1263HWa0812545201 | NEW | no | no | REI 60-A1 - A2,s1-d0 / A1 | 0 | no | 0 | no | Codetext | AllplanAttributes - W_Deckenanschluss: Gleitender Deckenanschluss Fall 01; ash_W_Trockenbau_Qualitäten: 1b
 | H2 Ebene +3 | WI-LB | 1263Wa 0812546407 | yes | Codetext | m² | Trockenbauarbeiten | Wand | Innenwand 1-Schalig | WI-LB | 0 | A | 11.25 | 1263HWa0812544148 | NEW | no | no | REI 60-A1 - A2,s1-d0 / A1 | 0 | no | 0 | no | Codetext | AllplanAttributes - W_Deckenanschluss: Gleitender Deckenanschluss Fall 01; ash_W_Trockenbau_Qualitäten: 1b
 | H2 Ebene +3 | WI-LB | 1263Wa 0812546902 | yes | Codetext | m² | Trockenbauarbeiten | Wand | Innenwand 1-Schalig | WI-LB | 0 | A | 11.25 | 1263HWa0812544133 | NEW | no | no | REI 60-A1 - A2,s1-d0 / A1 | 0 | no | 0 | no | Codetext | AllplanAttributes - W_Deckenanschluss: Gleitender Deckenanschluss Fall 01; ash_W_Trockenbau_Qualitäten: 1b
 | H2 Ebene +3 | WI-LB | 1263Wa 0812546898 | yes | Codetext | m² | Trockenbauarbeiten | Wand | Innenwand 1-Schalig | WI-LB | 0 | A | 11.25 | 1263HWa0812544132 | NEW | no | no | REI 60-A1 - A2,s1-d0 / A1 | 0 | no | 0 | no | Codetext | AllplanAttributes - W_Deckenanschluss: Gleitender Deckenanschluss Fall 01; ash_W_Trockenbau_Qualitäten: 1b
 | H2 Ebene +3 | WI-LB | 1263Wa 0812546920 | yes | Codetext | m² | Trockenbauarbeiten | Wand | Innenwand 1-Schalig | WI-LB | 0 | A | 11.25 | 1263HWa0812544105 | NEW | no | no | REI 60-A1 - A2,s1-d0 / A1 | 0 | no | 0 | no | Codetext | AllplanAttributes - W_Deckenanschluss: Gleitender Deckenanschluss Fall 01; ash_W_Trockenbau_Qualitäten: 1b
 | H2 Ebene +3 | Installationsraum | 1263Wa 0812601946 | yes | Codetext | m² | Trockenbauarbeiten | Wand | Installationswand | Installationsraum | 0 | A | 11.25 | 1263HWa0812601943 | NEW | no | no | 0 | 0 | no | 0 | no | Codetext | AllplanAttributes - W_Deckenanschluss: Gleitender Deckenanschluss Fall 01
 | H2 Ebene +3 | WI-VS | 1263Wa 0812601948 | yes | Codetext | m² | Trockenbauarbeiten | Wand | Installationswand | WI-VS | 0 | A | 11.25 | 1263HWa0812601943 | NEW | no | no | 0 | 0 | no | 0 | no | Codetext | AllplanAttributes - W_Deckenanschluss: Gleitender Deckenanschluss Fall 01; ash_W_Trockenbau_Qualitäten: 2
 | H2 Ebene +3 | WI-LB | 1263Wa 0812546928 | yes | Codetext | m² | Trockenbauarbeiten | Wand | Innenwand 1-Schalig | WI-LB | 0 | A | 11.25 | 1263HWa0812544104 | NEW | no | no | REI 60-A1 - A2,s1-d0 / A1 | 0 | no | 0 | no | Codetext | AllplanAttributes - W_Deckenanschluss: Gleitender Deckenanschluss Fall 01; ash_W_Trockenbau_Qualitäten: 1b
 | H2 Ebene +3 | WI-HW 60 | 1263Wa 0812546930 | yes | Codetext | m² | Trockenbauarbeiten | Wand | Innenwand 1-Schalig | WI-HW 60 | 0 | A | 11.25 | 1263HWa0812544482 | NEW | yes | no | REI-M 60-D,s2,d0 + A1 | 0 | no | 0 | no | Codetext | AllplanAttributes - ash D_Detailverweis: DT 8; ash D_Plannummer: D1613
 | H2 Ebene +3 | WI-HW 60 | 1263Wa 0812547457 | yes | Codetext | m² | Trockenbauarbeiten | Wand | Innenwand 1-Schalig | WI-HW 60 | 0 | A | 11.25 | 1263HWa0812545527 | NEW | yes | no | REI 60-A1 - D,s2-d0 +A1 | 0 | no | 0 | no | Codetext | AllplanAttributes - ash D_Detailverweis: DT 8; ash D_Plannummer: D1613
 | H2 Ebene +3 | WI-STB | 1263Wa 0812546937 | yes | Codetext | m² | Betonarbeiten | Wand | Innenwand 1-Schalig | WI-STB | 0 | A | 11.25 | 1263HWa0812546934 | NEW | yes | no | REI-M 60-A1 | 0 | no | 0 | yes | Codetext | AllplanAttributes - ash D_Detailverweis: DT 3; ash D_Plannummer: D1615; Text1: SB3
 | H2 Ebene +3 | WI-HW 60 | 1263Wa 0812546960 | yes | Codetext | m² | Trockenbauarbeiten | Wand | Innenwand 1-Schalig | WI-HW 60 | 0 | A | 11.25 | 1263HWa0812546789 | NEW | yes | no | REI 60-A1 - D,s2-d0 +A1 | 0 | no | 0 | no | Codetext | AllplanAttributes - ash D_Detailverweis: J1; ash D_Plannummer: D1651
 | H2 Ebene +3 | WI-HW 60 | 1263Wa 0812546187 | yes | Codetext | m² | Trockenbauarbeiten | Wand | Innenwand 1-Schalig | WI-HW 60 | 0 | A | 11.25 | 1263HWa0812545248 | NEW | yes | no | REI 60-A1 - A2,s1-d0 / A1 | 0 | no | 0 | no | Codetext
 | H2 Ebene +3 | WI-LB | 1263Wa 0812594385 | yes | Codetext | m² | Trockenbauarbeiten | Wand | Innenwand 1-Schalig | WI-LB | 0 | A | 11.25 | 1263HWa0812594383 | NEW | no | no | REI 60-A1 - D,s2-d0 +A1 | 0 | no | 42 | no | Codetext | AllplanAttributes - W_Deckenanschluss: Gleitender Deckenanschluss Fall 01; ash_W_Trockenbau_Qualitäten: 1b
 | H2 Ebene +3 | WI-STB | 1263Wa 0812547332 | yes | Codetext | m² | Betonarbeiten | Wand | Innenwand 1-Schalig | WI-STB | 0 | A | 11.25 | 1263HWa0812547294 | NEW | yes | no | REI 60-A1 - A2,s1-d0 / A1 | 0 | no | 0 | yes | Codetext
 | H2 Ebene +3 | WI-STB | 1263Wa 0812547298 | yes | Codetext | m² | Betonarbeiten | Wand | Innenwand 1-Schalig | WI-STB | 0 | A | 11.25 | 1263HWa0812547294 | NEW | yes | no | REI 60-A1 - A2,s1-d0 / A1 | 0 | no | 0 | yes | Codetext
 | H2 Ebene +3 | Installationsraum | 1263Wa 0812593409 | yes | Codetext | m² | Trockenbauarbeiten | Wand | Installationswand | Installationsraum | 0 | A | 11.25 | 1263HWa0812593379 | NEW | no | no | 0 | 0 | no | 0 | no | Codetext | AllplanAttributes - W_Deckenanschluss: Gleitender Deckenanschluss Fall 01
 | H2 Ebene +3 | WI-VS | 1263Wa 0812593408 | yes | Codetext | m² | Trockenbauarbeiten | Wand | Installationswand | WI-VS | 0 | A | 11.25 | 1263HWa0812593379 | NEW | no | no | 0 | 0 | no | 0 | no | Codetext | AllplanAttributes - W_Deckenanschluss: Gleitender Deckenanschluss Fall 01; ash_W_Trockenbau_Qualitäten: 3
 | H2 Ebene +3 | WI-LB | 1263Wa 0812547365 | yes | Codetext | m² | Trockenbauarbeiten | Wand | Innenwand 1-Schalig | WI-LB | 0 | A | 11.25 | 1263HWa0812547213 | NEW | no | no | REI 30 | 0 | no | 42 | no | Codetext | AllplanAttributes - W_Deckenanschluss: Gleitender Deckenanschluss Fall 01; ash_W_Trockenbau_Qualitäten: 1b
 | H2 Ebene +3 | WI-LB | 1263Wa 0812593412 | yes | Codetext | m² | Trockenbauarbeiten | Wand | Innenwand 1-Schalig | WI-LB | 0 | A | 11.25 | 1263HWa0812593394 | NEW | no | no | 0 | 0 | no | 42 | no | Codetext | AllplanAttributes - W_Deckenanschluss: Gleitender Deckenanschluss Fall 01; ash_W_Trockenbau_Qualitäten: 10a
 | H2 Ebene +3 | WI-LB | 1263Wa 0812979654 | yes | Codetext | m² | Trockenbauarbeiten | Wand | Innenwand 1-Schalig | WI-LB | 0 | A | 11.25 | 1263HWa0812843014 | NEW | no | no | REI 30 | 0 | no | 42 | no | Codetext | AllplanAttributes - W_Deckenanschluss: Gleitender Deckenanschluss Fall 01; ash_W_Trockenbau_Qualitäten: 1b
 | H2 Ebene +3 | WI-LB | 1263Wa 0812978765 | yes | Codetext | m² | Trockenbauarbeiten | Wand | Innenwand 1-Schalig | WI-LB | 0 | A | 11.25 | 1263HWa0812843014 | NEW | no | no | REI 30 | 0 | no | 42 | no | Codetext | AllplanAttributes - W_Deckenanschluss: Gleitender Deckenanschluss Fall 01; ash_W_Trockenbau_Qualitäten: 1b
 | H2 Ebene +3 | WI-LB | 1263Wa 0812979742 | yes | Codetext | m² | Trockenbauarbeiten | Wand | Innenwand 1-Schalig | WI-LB | 0 | A | 11.25 | 1263HWa0812843014 | NEW | no | no | REI 30 | 0 | no | 42 | no | Codetext | AllplanAttributes - W_Deckenanschluss: Gleitender Deckenanschluss Fall 01; ash_W_Trockenbau_Qualitäten: 18
 | H2 Ebene +3 | WI-LB | 1263Wa 0812978767 | yes | Codetext | m² | Trockenbauarbeiten | Wand | Innenwand 1-Schalig | WI-LB | 0 | A | 11.25 | 1263HWa0812843014 | NEW | no | no | REI 30 | 0 | no | 42 | no | Codetext | AllplanAttributes - W_Deckenanschluss: Gleitender Deckenanschluss Fall 01; ash_W_Trockenbau_Qualitäten: 18
 | H2 Ebene +3 | WI-LB | 1263Wa 0812978769 | yes | Codetext | m² | Trockenbauarbeiten | Wand | Innenwand 1-Schalig | WI-LB | 0 | A | 11.25 | 1263HWa0812843014 | NEW | no | no | REI 30 | 0 | no | 42 | no | Codetext | AllplanAttributes - W_Deckenanschluss: Gleitender Deckenanschluss Fall 01; ash_W_Trockenbau_Qualitäten: 1b
 | H2 Ebene +3 | WI-LB | 1263Wa 0812843244 | yes | Codetext | m² | Trockenbauarbeiten | Wand | Innenwand 1-Schalig | WI-LB | 0 | A | 11.25 | 1263HWa0812843014 | NEW | no | no | REI 30 | 0 | no | 42 | no | Codetext | AllplanAttributes - W_Deckenanschluss: Gleitender Deckenanschluss Fall 01; ash_W_Trockenbau_Qualitäten: 1b
 | H2 Ebene +3 | WI-LB | 1263Wa 0812975401 | yes | Codetext | m² | Trockenbauarbeiten | Wand | Innenwand 1-Schalig | WI-LB | 0 | A | 11.25 | 1263HWa0812843014 | NEW | no | no | REI 30 | 0 | no | 42 | no | Codetext | AllplanAttributes - W_Deckenanschluss: Gleitender Deckenanschluss Fall 01; ash_W_Trockenbau_Qualitäten: 1b
 | H2 Ebene +3 | WI-HW 60 | 1263Wa 0812547229 | yes | Codetext | m² | Trockenbauarbeiten | Wand | Innenwand 1-Schalig | WI-HW 60 | 0 | A | 11.25 | 1263HWa0812546998 | NEW | yes | no | REI-M 60-D,s2,d0 + A1 | 0 | no | 42 | no | Codetext | AllplanAttributes - ash D_Detailverweis: DT 7; ash D_Plannummer: D1613
 | H2 Ebene +3 | WI-HW 60 | 1263Wa 0812824831 | yes | Codetext | m² | Trockenbauarbeiten | Wand | Innenwand 1-Schalig | WI-HW 60 | 0 | A | 11.25 | 1263HWa0812824830 | NEW | yes | no | REI-M 60-D,s2,d0 + A1 | 0 | no | 42 | no | Codetext | AllplanAttributes - ash D_Detailverweis: DT 8; ash D_Plannummer: D1613
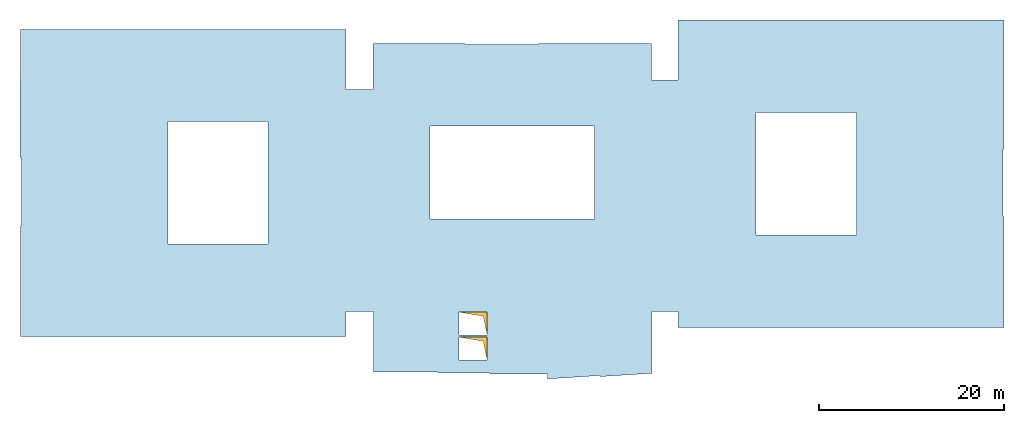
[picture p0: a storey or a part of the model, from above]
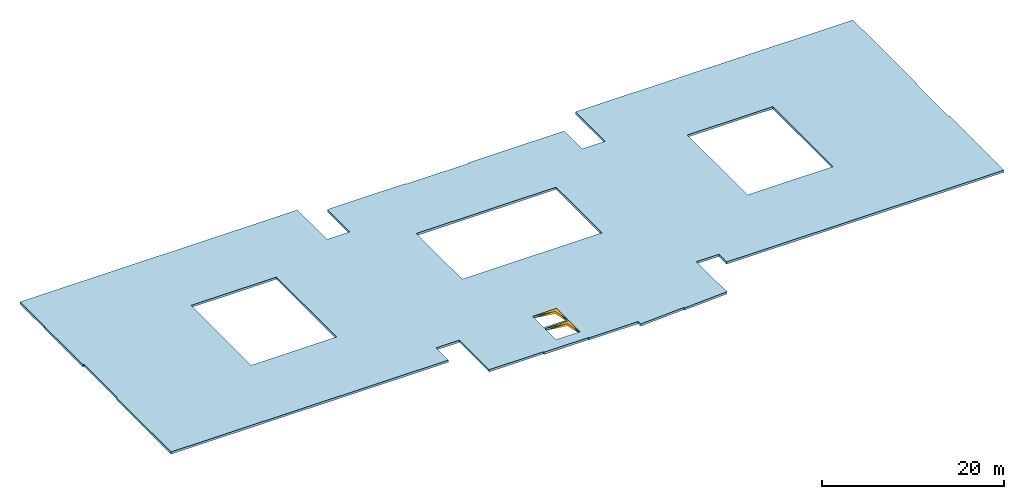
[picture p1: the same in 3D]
Properties of the parts of a building model (IFC4), part 48 of 80

# IfcWall (6826)
Name | In | Material | Allright_Bauteil_ID | 2D Interaktion | Codetext | Abrechnungsart | Gewerk | Objektname | Bezeichnung | AllplanAttributes, Material | Typ = SurfaceSpreadOfFlame | Brandschutzklasse | OKFF | P_ID | Status | LoadBearing | IsExternal | FireRating | ThermalTransmittance (W/K/m2) | Combustible | AcousticRating | Compartmentation | Reference
 | H2 Ebene +3 | WI-LB | 1263Wa 0812833063 | yes | Codetext | m² | Trockenbauarbeiten | Wand | Innenwand 1-Schalig | WI-LB | 0 | A | 11.25 | 1263HWa0812833053 | NEW | no | no | 0 | 0 | no | 42 | no | Codetext | AllplanAttributes - W_Deckenanschluss: Gleitender Deckenanschluss Fall 01; ash_W_Trockenbau_Qualitäten: 10a
 | H2 Ebene +3 | WI-LB | 1263Wa 0812839292 | yes | Codetext | m² | Trockenbauarbeiten | Wand | Innenwand 1-Schalig | WI-LB | 0 | A | 11.25 | 1263HWa0812839278 | NEW | no | no | 0 | 0 | no | 42 | no | Codetext | AllplanAttributes - W_Deckenanschluss: Gleitender Deckenanschluss Fall 01; ash_W_Trockenbau_Qualitäten: 10a
 | H2 Ebene +3 | Installationsraum | 1263Wa 0812839369 | yes | Codetext | m² | Trockenbauarbeiten | Wand | Installationswand | Installationsraum | 0 | A | 11.25 | 1263HWa0812839368 | NEW | no | no | 0 | 0 | no | 0 | no | Codetext | AllplanAttributes - W_Deckenanschluss: Gleitender Deckenanschluss Fall 01
 | H2 Ebene +3 | WI-VS | 1263Wa 0812839370 | yes | Codetext | m² | Trockenbauarbeiten | Wand | Installationswand | WI-VS | 0 | A | 11.25 | 1263HWa0812839368 | NEW | no | no | 0 | 0 | no | 0 | no | Codetext | AllplanAttributes - W_Deckenanschluss: Gleitender Deckenanschluss Fall 01; ash_W_Trockenbau_Qualitäten: 3
 | H2 Ebene +3 | WI-LB | 1263Wa 0812988746 | yes | Codetext | m² | Trockenbauarbeiten | Wand | Innenwand 1-Schalig | WI-LB | 0 | A | 11.25 | 1263HWa0812594456 | NEW | no | no | 0 | 0 | no | 42 | no | Codetext | AllplanAttributes - W_Deckenanschluss: Gleitender Deckenanschluss Fall 01; ash_W_Trockenbau_Qualitäten: 11
 | H2 Ebene +3 | WI-LB | 1263Wa 0812594458 | yes | Codetext | m² | Trockenbauarbeiten | Wand | Innenwand 1-Schalig | WI-LB | 0 | A | 11.25 | 1263HWa0812594456 | NEW | no | no | 0 | 0 | no | 42 | no | Codetext | AllplanAttributes - W_Deckenanschluss: Gleitender Deckenanschluss Fall 01; ash_W_Trockenbau_Qualitäten: 10a
 | H2 Ebene +3 | WI-LB | 1263Wa 0812547135 | yes | Codetext | m² | Trockenbauarbeiten | Wand | Innenwand 1-Schalig | WI-LB | 0 | A | 11.25 | 1263HWa0812546999 | NEW | no | no | REI 30 | 0 | no | 42 | no | Codetext | AllplanAttributes - W_Deckenanschluss: Gleitender Deckenanschluss Fall 01; ash_W_Trockenbau_Qualitäten: 1b
 | H2 Ebene +3 | WI-HW 60 | 1263Wa 0812824924 | yes | Codetext | m² | Trockenbauarbeiten | Wand | Innenwand 1-Schalig | WI-HW 60 | 0 | A | 11.25 | 1263HWa0812824923 | NEW | yes | no | REI-M 60-D,s2,d0 + A1 | 0 | no | 42 | no | Codetext | AllplanAttributes - ash D_Detailverweis: DT 8; ash D_Plannummer: D1613
 | H2 Ebene +3 | WI-HW 60 | 1263Wa 0812824838 | yes | Codetext | m² | Trockenbauarbeiten | Wand | Innenwand 1-Schalig | WI-HW 60 | 0 | A | 11.25 | 1263HWa0812824837 | NEW | yes | no | REI-M 60-D,s2,d0 + A1 | 0 | no | 42 | no | Codetext | AllplanAttributes - ash D_Detailverweis: DT 7; ash D_Plannummer: D1613
 | H2 Ebene +3 | Installationsraum | 1263Wa 0812840744 | yes | Codetext | m² | Trockenbauarbeiten | Wand | Installationswand | Installationsraum | 0 | A | 11.25 | 1263HWa0812840743 | NEW | no | no | 0 | 0 | no | 0 | no | Codetext | AllplanAttributes - W_Deckenanschluss: Gleitender Deckenanschluss Fall 01
 | H2 Ebene +3 | WI-VS | 1263Wa 0812840745 | yes | Codetext | m² | Trockenbauarbeiten | Wand | Installationswand | WI-VS | 0 | A | 11.25 | 1263HWa0812840743 | NEW | no | no | 0 | 0 | no | 0 | no | Codetext | AllplanAttributes - W_Deckenanschluss: Gleitender Deckenanschluss Fall 01; ash_W_Trockenbau_Qualitäten: 3
 | H2 Ebene +3 | Installationsraum | 1263Wa 0812841032 | yes | Codetext | m² | Trockenbauarbeiten | Wand | Installationswand | Installationsraum | 0 | A | 11.25 | 1263HWa0812841030 | NEW | no | no | 0 | 0 | no | 0 | no | Codetext | AllplanAttributes - W_Deckenanschluss: Gleitender Deckenanschluss Fall 01
 | H2 Ebene +3 | WI-VS | 1263Wa 0812841033 | yes | Codetext | m² | Trockenbauarbeiten | Wand | Installationswand | WI-VS | 0 | A | 11.25 | 1263HWa0812841030 | NEW | no | no | 0 | 0 | no | 0 | no | Codetext | AllplanAttributes - W_Deckenanschluss: Gleitender Deckenanschluss Fall 01; ash_W_Trockenbau_Qualitäten: 3
 | H2 Ebene +3 | Installationsraum | 1263Wa 0812840779 | yes | Codetext | m² | Trockenbauarbeiten | Wand | Installationswand | Installationsraum | 0 | A | 11.25 | 1263HWa0812840778 | NEW | no | no | 0 | 0 | no | 0 | no | Codetext | AllplanAttributes - W_Deckenanschluss: Gleitender Deckenanschluss Fall 01
 | H2 Ebene +3 | WI-VS | 1263Wa 0812840780 | yes | Codetext | m² | Trockenbauarbeiten | Wand | Installationswand | WI-VS | 0 | A | 11.25 | 1263HWa0812840778 | NEW | no | no | 0 | 0 | no | 0 | no | Codetext | AllplanAttributes - W_Deckenanschluss: Gleitender Deckenanschluss Fall 01; ash_W_Trockenbau_Qualitäten: 3
 | H2 Ebene +3 | WI-STB | 1263Wa 0812787100 | yes | Codetext | m² | Betonarbeiten | Wand | Innenwand 1-Schalig | WI-STB | 0 | A | 11.25 | 1263HWa0812786878 | NEW | yes | no | REI 60-A1 - A2,s1-d0 / A1 | 0 | no | 0 | no | Codetext
 | H2 Ebene +3 | WI-STB | 1263Wa 0812550822 | yes | Codetext | m² | Betonarbeiten | Wand | Innenwand 1-Schalig | WI-STB | 0 | A | 11.25 | 1263HWa0812550813 | NEW | yes | no | REI 60-A1 - A2,s1-d0 / A1 | 0 | no | 0 | no | Codetext
 | H2 Ebene +3 | WI-STB | 1263Wa 0812547722 | yes | Codetext | m² | Betonarbeiten | Wand | Innenwand 1-Schalig | WI-STB | 0 | A | 11.25 | 1263HWa0812544977 | NEW | yes | no | REI 60-A1 - A2,s1-d0 / A1 | 0 | no | 0 | no | Codetext
 | H2 Ebene +3 | WI-LB | 1263Wa 0812964104 | yes | Codetext | m² | Trockenbauarbeiten | Wand | Innenwand 1-Schalig | WI-LB | 0 | A | 7.5 | 1213HWa0812969822 | NEW | no | no | REI 60-A1 - D,s2-d0 /A1 | 0 | no | 0 | no | Codetext | AllplanAttributes - ash_W_Trockenbau_Qualitäten: 16
 | H2 Ebene +3 | WI-STB | 1263Wa 0812546058 | yes | Codetext | m² | Betonarbeiten | Wand | Innenwand 1-Schalig | WI-STB | 0 | A | 11.25 | 1263HWa0812544974 | NEW | no | no | REI 60-A1 - A2,s1-d0 / A1 | 0 | no | 0 | no | Codetext | AllplanAttributes - Ortscode_Geschoßbezeichnung: E03
 | H2 Ebene +3 | WI-STB | 1263Wa 0812550772 | yes | Codetext | m² | Betonarbeiten | Wand | Innenwand 1-Schalig | WI-STB | 0 | A | 11.25 | 1263HWa0812550766 | NEW | no | no | REI 60-A1 - A2,s1-d0 / A1 | 0 | no | 0 | no | Codetext
 | H2 Ebene +3 | WI-LB | 1263Wa 0812963942 | yes | Codetext | m² | Trockenbauarbeiten | Wand | Innenwand 1-Schalig | WI-LB | 0 | A | 7.5 | 1213HWa0812969822 | NEW | no | no | REI 60-A1 - D,s2-d0 /A1 | 0 | no | 0 | no | Codetext | AllplanAttributes - ash_W_Trockenbau_Qualitäten: 16
 | H2 Ebene +3 | WI-STB | 1263Wa 0812546956 | yes | Codetext | m² | Betonarbeiten | Wand | Innenwand 1-Schalig | WI-STB | 0 | A | 11.25 | 1263HWa0812544980 | NEW |  | no | REI 60-A1 - A2,s1-d0 / A1 | 0 | no | 0 | no | Codetext
 | H2 Ebene +3 | WI-LB | 1263Wa 0812821139 | yes | Codetext | m² | Trockenbauarbeiten | Wand | Innenwand 1-Schalig | WI-LB | 0 | A | 11.25 | 1263HWa0812544980 | NEW |  | no | REI 60-A1 - D,s2-d0 +A1 | 0 | no | 0 | no | Codetext | AllplanAttributes - ash_W_Trockenbau_Qualitäten: 9
 | H2 Ebene +3 | WI-LB | 1263Wa 0812546974 | yes | Codetext | m² | Trockenbauarbeiten | Wand | Innenwand 1-Schalig | WI-LB | 0 | A | 11.25 | 1263HWa0812544490 | NEW |  | no | REI 60-A1 - D,s2-d0 +A1 | 0 | no | 0 | no | Codetext | AllplanAttributes - ash_W_Trockenbau_Qualitäten: 9
 | H2 Ebene +3 | WI-STB | 1263Wa 0812820817 | yes | Codetext | m² | Betonarbeiten | Wand | Innenwand 1-Schalig | WI-STB | 0 | A | 11.25 | 1263HWa0812544490 | NEW |  | no | REI 60-A1 - A2,s1-d0 / A1 | 0 | no | 0 | no | Codetext
 | H2 Ebene +3 | WI-STB | 1263Wa 0812546126 | yes | Codetext | m² | Betonarbeiten | Wand | Innenwand 1-Schalig | WI-STB | 0 | A | 11.25 | 1263HWa0812544976 | NEW | yes | no | REI 60-A1 - A2,s1-d0 / A1 | 0 | no | 0 | no | Codetext | AllplanAttributes - Ortscode_Geschoßbezeichnung: E03
 | H2 Ebene +3 | WI-STB | 1263Wa 0812546869 | yes | Codetext | m² | Betonarbeiten | Wand | Innenwand 1-Schalig | WI-STB | 0 | A | 11.25 | 1263HWa0812546824 | NEW | yes | no | REI-M 60-A1 | 0 | no | 47 | no | Codetext | AllplanAttributes - ash D_Detailverweis: DT 3; ash D_Plannummer: D1615; Text1: SB3
 | H2 Ebene +3 | WI-STB | 1263Wa 0812981758 | yes | Codetext | m² | Betonarbeiten | Wand | Innenwand 1-Schalig | WI-STB | 0 | A | 11.25 | 1263HWa0812544236 | NEW | yes | no | REI-M 60-A1 | 0 | no | 0 | no | Codetext | AllplanAttributes - ash D_Detailverweis: DT 3; ash D_Plannummer: D1615; Text1: SB3
 | H2 Ebene +3 | WI-STB | 1263Wa 0812981753 | yes | Codetext | m² | Betonarbeiten | Wand | Innenwand 1-Schalig | WI-STB | 0 | A | 11.25 | 1263HWa0812544236 | NEW | yes | no | REI-M 60-A1 | 0 | no | 0 | no | Codetext | AllplanAttributes - ash D_Detailverweis: DT 3; ash D_Plannummer: D1615; Text1: SB3
 | H2 Ebene +3 | WI-STB | 1263Wa 0812546107 | yes | Codetext | m² | Betonarbeiten | Wand | Innenwand 1-Schalig | WI-STB | 0 | A | 11.25 | 1263HWa0812545524 | NEW | no | no | REI 60-A1 - A2,s1-d0 / A1 | 0 | no | 0 | no | Codetext | AllplanAttributes - Text1: SB3
 | H2 Ebene +3 | WI-LB | 1263Wa 0812821255 | yes | Codetext | m² | Trockenbauarbeiten | Wand | Innenwand 1-Schalig | WI-LB | 0 | A | 11.25 | 1263HWa0812545524 | NEW | no | no | REI 60-A1 - D,s2-d0 +A1 | 0 | no | 0 | no | Codetext
 | H2 Ebene +3 | WI-LB | 1263Wa 0812594303 | yes | Codetext | m² | Trockenbauarbeiten | Wand | Innenwand 1-Schalig | WI-LB | 0 | A | 11.25 | 1263HWa0812594301 | NEW | no | no | 0 | 0 | no | 0 | no | Codetext | AllplanAttributes - W_Deckenanschluss: Gleitender Deckenanschluss Fall 01; ash_W_Trockenbau_Qualitäten: 1b
 | H2 Ebene +3 | Installationsraum | 1263Wa 0812839397 | yes | Codetext | m² | Trockenbauarbeiten | Wand | Installationswand | Installationsraum | 0 | A | 11.25 | 1263HWa0812839396 | NEW | no | no | 0 | 0 | no | 0 | no | Codetext | AllplanAttributes - W_Deckenanschluss: Gleitender Deckenanschluss Fall 01
 | H2 Ebene +3 | WI-VS | 1263Wa 0812839398 | yes | Codetext | m² | Trockenbauarbeiten | Wand | Installationswand | WI-VS | 0 | A | 11.25 | 1263HWa0812839396 | NEW | no | no | 0 | 0 | no | 0 | no | Codetext | AllplanAttributes - W_Deckenanschluss: Gleitender Deckenanschluss Fall 01; ash_W_Trockenbau_Qualitäten: 3
 | H2 Ebene +3 | WI-STB | 1263Wa 0812981708 | yes | Codetext | m² | Betonarbeiten | Wand | Innenwand 1-Schalig | WI-STB | 0 | A | 11.25 | 1263HWa0812544236 | NEW | yes | no | REI-M 60-A1 | 0 | no | 0 | no | Codetext | AllplanAttributes - ash D_Detailverweis: DT 3; ash D_Plannummer: D1615; Text1: SB3
 | H2 Ebene +3 | WI-STB | 1263Wa 0813026477 | yes | Codetext | m² | Betonarbeiten | Wand | Innenwand 1-Schalig | WI-STB | 0 | A | 11.25 | 1263HWa0812544236 | NEW | yes | no | REI-M 60-A1 | 0 | no | 0 | no | Codetext | AllplanAttributes - ash D_Detailverweis: DT 3; ash D_Plannummer: D1615; Text1: SB3
 | H2 Ebene +3 | WI-LB | 1263Wa 0812547241 | yes | Codetext | m² | Trockenbauarbeiten | Wand | Innenwand 1-Schalig | WI-LB | 0 | A | 11.25 | 1263HWa0812545256 | NEW | no | no | REI 60-A1 - D,s2-d0 +A1 | 0 | no | 0 | no | Codetext | AllplanAttributes - Ortscode_Geschoßbezeichnung: E03; W_Deckenanschluss: Gleitender Deckenanschluss Fall 01; ash_W_Trockenbau_Qualitäten: 1b
 | H2 Ebene +3 | WI-LB | 1263Wa 0812547334 | yes | Codetext | m² | Trockenbauarbeiten | Wand | Innenwand 1-Schalig | WI-LB | 0 | A | 11.25 | 1263HWa0812547284 | NEW | no | no | REI 30 | 0 | no | 42 | no | Codetext | AllplanAttributes - Ortscode_Geschoßbezeichnung: E03; W_Deckenanschluss: Gleitender Deckenanschluss Fall 01; ash_W_Trockenbau_Qualitäten: 1b
 | H2 Ebene +3 | WI-LB | 1263Wa 0812547131 | yes | Codetext | m² | Trockenbauarbeiten | Wand | Innenwand 1-Schalig | WI-LB | 0 | A | 11.25 | 1263HWa0812545272 | NEW | no | no | REI 30 | 0 | no | 42 | no | Codetext | AllplanAttributes - W_Deckenanschluss: Gleitender Deckenanschluss Fall 01; ash_W_Trockenbau_Qualitäten: 1b
 | H2 Ebene +3 | WI-STB | 1263Wa 0812989927 | yes | Codetext | m² | Betonarbeiten | Wand | Innenwand 1-Schalig | WI-STB | 0 | A | 11.25 | 1263HWa0812547294 | NEW |  | no | REI 60-A1 - A2,s1-d0 / A1 | 0 | no | 0 | yes | Codetext
 | H2 Ebene +3 | WI-LB | 1263Wa 0813026738 | yes | Codetext | m² | Trockenbauarbeiten | Wand | Innenwand 1-Schalig | WI-LB | 0 | A | 11.25 | 1263HWa0812544980 | NEW |  | no | REI 60-A1 - D,s2-d0 +A1 | 0 | no | 0 | no | Codetext | AllplanAttributes - ash_W_Trockenbau_Qualitäten: 9
 | H2 Ebene +3 | WI-LB | 1263Wa 0812547148 | yes | Codetext | m² | Trockenbauarbeiten | Wand | Innenwand 1-Schalig | WI-LB | 0 | A | 11.25 | 1263HWa0812544980 | NEW |  | no | REI 60-A1 - D,s2-d0 +A1 | 0 | no | 0 | no | Codetext | AllplanAttributes - ash_W_Trockenbau_Qualitäten: 9
 | H2 Ebene +3 | WI-STB | 1263Wa 0813026900 | yes | Codetext | m² | Betonarbeiten | Wand | Innenwand 1-Schalig | WI-STB | 0 | A | 11.25 | 1263HWa0812545399 | NEW |  | no | REI 60-A1 - A2,s1-d0 / A1 | 0 | no | 42 | yes | Codetext
 | H2 Ebene +3 | WI-LB | 1263Wa 0812547129 | yes | Codetext | m² | Trockenbauarbeiten | Wand | Innenwand 1-Schalig | WI-LB | 0 | A | 11.25 | 1263HWa0812544980 | NEW |  | no | REI 60-A1 - D,s2-d0 +A1 | 0 | no | 0 | no | Codetext | AllplanAttributes - ash_W_Trockenbau_Qualitäten: 9
 | H2 Ebene +3 | WI-STB | 1263Wa 0813027028 | yes | Codetext | m² | Betonarbeiten | Wand | Innenwand 1-Schalig | WI-STB | 0 | A | 11.25 | 1263HWa0812545399 | NEW |  | no | REI 60-A1 - A2,s1-d0 / A1 | 0 | no | 42 | yes | Codetext
 | H2 Ebene +3 | WI-LB | 1263Wa 0813027432 | yes | Codetext | m² | Trockenbauarbeiten | Wand | Innenwand 1-Schalig | WI-LB | 0 | A | 11.25 | 1263HWa0812544980 | NEW |  | no | REI 60-A1 - D,s2-d0 +A1 | 0 | no | 0 | no | Codetext | AllplanAttributes - ash_W_Trockenbau_Qualitäten: 9
 | H2 Ebene +3 | WI-LB | 1263Wa 0813027443 | yes | Codetext | m² | Trockenbauarbeiten | Wand | Innenwand 1-Schalig | WI-LB | 0 | A | 11.25 | 1263HWa0812544980 | NEW |  | no | REI 60-A1 - D,s2-d0 +A1 | 0 | no | 0 | no | Codetext | AllplanAttributes - ash_W_Trockenbau_Qualitäten: 9
 | H2 Ebene +3 | WI-LB | 1263Wa 0813027558 | yes | Codetext | m² | Trockenbauarbeiten | Wand | Innenwand 1-Schalig | WI-LB | 0 | A | 11.25 | 1263HWa0812544980 | NEW |  | no | REI 60-A1 - D,s2-d0 +A1 | 0 | no | 0 | no | Codetext | AllplanAttributes - ash_W_Trockenbau_Qualitäten: 9
 | H2 Ebene +3 | WI-LB | 1263Wa 0813026710 | yes | Codetext | m² | Trockenbauarbeiten | Wand | Innenwand 1-Schalig | WI-LB | 0 | A | 11.25 | 1263HWa0812544980 | NEW |  | no | REI 60-A1 - D,s2-d0 +A1 | 0 | no | 0 | no | Codetext | AllplanAttributes - ash_W_Trockenbau_Qualitäten: 9
 | H2 Ebene +3 | WI-LB | 1263Wa 0812547237 | yes | Codetext | m² | Trockenbauarbeiten | Wand | Innenwand 1-Schalig | WI-LB | 0 | A | 11.25 | 1263HWa0812545273 | NEW | no | no | REI 60-A1 - D,s2-d0 +A1 | 0 | no | 42 | no | Codetext | AllplanAttributes - W_Deckenanschluss: Gleitender Deckenanschluss Fall 01; ash_W_Trockenbau_Qualitäten: 1b
 | H2 Ebene +3 | Installationsraum | 1263Wa 0812772337 | yes | Codetext | m² | Trockenbauarbeiten | Wand | Installationswand | Installationsraum | 0 | A | 11.25 | 1263HWa0812772336 | NEW | no | no | 0 | 0 | no | 0 | no | Codetext | AllplanAttributes - W_Deckenanschluss: Gleitender Deckenanschluss Fall 01
 | H2 Ebene +3 | WI-VS | 1263Wa 0812772338 | yes | Codetext | m² | Trockenbauarbeiten | Wand | Installationswand | WI-VS | 0 | A | 11.25 | 1263HWa0812772336 | NEW | no | no | 0 | 0 | no | 0 | no | Codetext | AllplanAttributes - W_Deckenanschluss: Gleitender Deckenanschluss Fall 01; ash_W_Trockenbau_Qualitäten: 2
 | H2 Ebene +3 | Installationsraum | 1263Wa 0812769296 | yes | Codetext | m² | Trockenbauarbeiten | Wand | Installationswand | Installationsraum | 0 | A | 11.25 | 1263HWa0812769295 | NEW | no | no | 0 | 0 | no | 0 | no | Codetext | AllplanAttributes - W_Deckenanschluss: Gleitender Deckenanschluss Fall 01
 | H2 Ebene +3 | WI-VS | 1263Wa 0812769297 | yes | Codetext | m² | Trockenbauarbeiten | Wand | Installationswand | WI-VS | 0 | A | 11.25 | 1263HWa0812769295 | NEW | no | no | 0 | 0 | no | 0 | no | Codetext | AllplanAttributes - W_Deckenanschluss: Gleitender Deckenanschluss Fall 01; ash_W_Trockenbau_Qualitäten: 3
 | H2 Ebene +3 | Installationsraum | 1263Wa 0812769873 | yes | Codetext | m² | Trockenbauarbeiten | Wand | Installationswand | Installationsraum | 0 | A | 11.25 | 1263HWa0812769872 | NEW | no | no | 0 | 0 | no | 0 | no | Codetext | AllplanAttributes - W_Deckenanschluss: Gleitender Deckenanschluss Fall 01
 | H2 Ebene +3 | WI-VS | 1263Wa 0812769874 | yes | Codetext | m² | Trockenbauarbeiten | Wand | Installationswand | WI-VS | 0 | A | 11.25 | 1263HWa0812769872 | NEW | no | no | 0 | 0 | no | 0 | no | Codetext | AllplanAttributes - W_Deckenanschluss: Gleitender Deckenanschluss Fall 01; ash_W_Trockenbau_Qualitäten: 3
 | H2 Ebene +3 | WI-LB | 1263Wa 0813026845 | yes | Codetext | m² | Trockenbauarbeiten | Wand | Innenwand 1-Schalig | WI-LB | 0 | A | 11.25 | 1263HWa0812544980 | NEW |  | no | REI 60-A1 - D,s2-d0 +A1 | 0 | no | 0 | no | Codetext | AllplanAttributes - ash_W_Trockenbau_Qualitäten: 9
 | H2 Ebene +3 | WI-LB | 1263Wa 0813027395 | yes | Codetext | m² | Trockenbauarbeiten | Wand | Innenwand 1-Schalig | WI-LB | 0 | A | 11.25 | 1263HWa0812544980 | NEW |  | no | REI 60-A1 - D,s2-d0 +A1 | 0 | no | 0 | no | Codetext | AllplanAttributes - ash_W_Trockenbau_Qualitäten: 9
 | H2 Ebene +3 | WI-LB | 1263Wa 0813013567 | yes | Codetext | m² | Trockenbauarbeiten | Wand | Innenwand 1-Schalig | WI-LB | 0 | A | 11.25 | 1263HWa0812544221 | NEW | no | no | REI 60-A1 - A2,s1-d0 / A1 | 0 | no | 0 | no | Codetext | AllplanAttributes - W_Deckenanschluss: Gleitender Deckenanschluss Fall 01; ash_W_Trockenbau_Qualitäten: 1b
 | H2 Ebene +3 | WI-LB | 1263Wa 0812799791 | yes | Codetext | m² | Trockenbauarbeiten | Wand | Innenwand 1-Schalig | WI-LB | 0 | A | 11.25 | 1263HWa0812799789 | NEW | no | no | REI 60-A1 - A2,s1-d0 / A1 | 0 | no | 0 | no | Codetext | AllplanAttributes - W_Deckenanschluss: Gleitender Deckenanschluss Fall 01; ash_W_Trockenbau_Qualitäten: 1b
 | H2 Ebene +3 | WI-LB | 1263Wa 0813013546 | yes | Codetext | m² | Trockenbauarbeiten | Wand | Innenwand 1-Schalig | WI-LB | 0 | A | 11.25 | 1263HWa0812545216 | NEW | no | no | REI 60-A1 - A2,s1-d0 / A1 | 0 | no | 0 | no | Codetext | AllplanAttributes - W_Deckenanschluss: Gleitender Deckenanschluss Fall 01; ash_W_Trockenbau_Qualitäten: 1b
 | H2 Ebene +3 | WI-LB | 1263Wa 0812799991 | yes | Codetext | m² | Trockenbauarbeiten | Wand | Innenwand 1-Schalig | WI-LB | 0 | A | 11.25 | 1263HWa0812799989 | NEW | no | no | REI 60-A1 - A2,s1-d0 / A1 | 0 | no | 0 | no | Codetext | AllplanAttributes - W_Deckenanschluss: Gleitender Deckenanschluss Fall 01; ash_W_Trockenbau_Qualitäten: 1b
 | H2 Ebene +3 | WI-GKF | 1263Wa 0812799539 | yes | Codetext | m² | Trockenbauarbeiten | Wand | "BS-Beplankung; 2-fach Gipsfaserplatten" | WI-GKF | 0 | A | 11.25 | 1263HWa0812799528 | NEW | no | no |  | 0 | no | 0 | no | Codetext
 | H2 Ebene +3 | WI-GKF | 1263Wa 0812799623 | yes | Codetext | m² | Trockenbauarbeiten | Wand | "BS-Beplankung; 2-fach Gipsfaserplatten" | WI-GKF | 0 | A | 11.25 | 1263HWa0812799613 | NEW | no | no |  | 0 | no | 0 | no | Codetext
 | H2 Ebene +3 | WI-GKF | 1263Wa 0812799640 | yes | Codetext | m² | Trockenbauarbeiten | Wand | "BS-Beplankung; 2-fach Gipsfaserplatten" | WI-GKF | 0 | A | 11.25 | 1263HWa0812799633 | NEW | no | no |  | 0 | no | 0 | no | Codetext
 | H2 Ebene +3 | WI-GKF | 1263Wa 0812800071 | yes | Codetext | m² | Trockenbauarbeiten | Wand | "BS-Beplankung; 2-fach Gipsfaserplatten" | WI-GKF | 0 | A | 11.25 | 1263HWa0812800061 | NEW | no | no |  | 0 | no | 0 | no | Codetext
 | H2 Ebene +3 | WI-GKF | 1263Wa 0812800070 | yes | Codetext | m² | Trockenbauarbeiten | Wand | "BS-Beplankung; 2-fach Gipsfaserplatten" | WI-GKF | 0 | A | 11.25 | 1263HWa0812800062 | NEW | no | no |  | 0 | no | 0 | no | Codetext
 | H2 Ebene +3 | WI-GKF | 1263Wa 0812799642 | yes | Codetext | m² | Trockenbauarbeiten | Wand | "BS-Beplankung; 2-fach Gipsfaserplatten" | WI-GKF | 0 | A | 11.25 | 1263HWa0812799635 | NEW | no | no |  | 0 | no | 0 | no | Codetext
 | H2 Ebene +3 | WI-GKF | 1263Wa 0812799643 | yes | Codetext | m² | Trockenbauarbeiten | Wand | "BS-Beplankung; 2-fach Gipsfaserplatten" | WI-GKF | 0 | A | 11.25 | 1263HWa0812799632 | NEW | no | no |  | 0 | no | 0 | no | Codetext
 | H2 Ebene +3 | WI-GKF | 1263Wa 0812800856 | yes | Codetext | m² | Trockenbauarbeiten | Wand | "BS-Beplankung; 2-fach Gipsfaserplatten" | WI-GKF | 0 | A | 11.25 | 1263HWa0812800850 | NEW | no | no |  | 0 | no | 0 | no | Codetext
 | H2 Ebene +3 | WI-GKF | 1263Wa 0812800069 | yes | Codetext | m² | Trockenbauarbeiten | Wand | "BS-Beplankung; 2-fach Gipsfaserplatten" | WI-GKF | 0 | A | 11.25 | 1263HWa0812800063 | NEW | no | no |  | 0 | no | 0 | no | Codetext
 | H2 Ebene +3 | WI-GKF | 1263Wa 0812799538 | yes | Codetext | m² | Trockenbauarbeiten | Wand | "BS-Beplankung; 2-fach Gipsfaserplatten" | WI-GKF | 0 | A | 11.25 | 1263HWa0812799531 | NEW | no | no |  | 0 | no | 0 | no | Codetext
 | H2 Ebene +3 | WI-GKF | 1263Wa 0812799620 | yes | Codetext | m² | Trockenbauarbeiten | Wand | "BS-Beplankung; 2-fach Gipsfaserplatten" | WI-GKF | 0 | A | 11.25 | 1263HWa0812799612 | NEW | no | no |  | 0 | no | 0 | no | Codetext
 | H2 Ebene +3 | WI-GKF | 1263Wa 0812800858 | yes | Codetext | m² | Trockenbauarbeiten | Wand | "BS-Beplankung; 2-fach Gipsfaserplatten" | WI-GKF | 0 | A | 11.25 | 1263HWa0812800848 | NEW | no | no |  | 0 | no | 0 | no | Codetext
 | H2 Ebene +3 | WI-GKF | 1263Wa 0812799622 | yes | Codetext | m² | Trockenbauarbeiten | Wand | "BS-Beplankung; 2-fach Gipsfaserplatten" | WI-GKF | 0 | A | 11.25 | 1263HWa0812799614 | NEW | no | no |  | 0 | no | 0 | no | Codetext
 | H2 Ebene +3 | WI-GKF | 1263Wa 0812800068 | yes | Codetext | m² | Trockenbauarbeiten | Wand | "BS-Beplankung; 2-fach Gipsfaserplatten" | WI-GKF | 0 | A | 11.25 | 1263HWa0812800060 | NEW | no | no |  | 0 | no | 0 | no | Codetext
 | H2 Ebene +3 | WI-GKF | 1263Wa 0812799537 | yes | Codetext | m² | Trockenbauarbeiten | Wand | "BS-Beplankung; 2-fach Gipsfaserplatten" | WI-GKF | 0 | A | 11.25 | 1263HWa0812799530 | NEW | no | no |  | 0 | no | 0 | no | Codetext
 | H2 Ebene +3 | WI-GKF | 1263Wa 0812799641 | yes | Codetext | m² | Trockenbauarbeiten | Wand | "BS-Beplankung; 2-fach Gipsfaserplatten" | WI-GKF | 0 | A | 11.25 | 1263HWa0812799634 | NEW | no | no |  | 0 | no | 0 | no | Codetext
 | H2 Ebene +3 | WI-GKF | 1263Wa 0812800857 | yes | Codetext | m² | Trockenbauarbeiten | Wand | "BS-Beplankung; 2-fach Gipsfaserplatten" | WI-GKF | 0 | A | 11.25 | 1263HWa0812800849 | NEW | no | no |  | 0 | no | 0 | no | Codetext
 | H2 Ebene +3 | WI-GKF | 1263Wa 0812800855 | yes | Codetext | m² | Trockenbauarbeiten | Wand | "BS-Beplankung; 2-fach Gipsfaserplatten" | WI-GKF | 0 | A | 11.25 | 1263HWa0812800847 | NEW | no | no |  | 0 | no | 0 | no | Codetext
 | H2 Ebene +3 | WI-GKF | 1263Wa 0812799536 | yes | Codetext | m² | Trockenbauarbeiten | Wand | "BS-Beplankung; 2-fach Gipsfaserplatten" | WI-GKF | 0 | A | 11.25 | 1263HWa0812799529 | NEW | no | no |  | 0 | no | 0 | no | Codetext
 | H2 Ebene +3 | WI-GKF | 1263Wa 0812800878 | yes | Codetext | m² | Trockenbauarbeiten | Wand | "BS-Beplankung; 2-fach Gipsfaserplatten" | WI-GKF | 0 | A | 11.25 | 1263HWa0812800867 | NEW | no | no |  | 0 | no | 0 | no | Codetext
 | H2 Ebene +3 | WI-GKF | 1263Wa 0812800875 | yes | Codetext | m² | Trockenbauarbeiten | Wand | "BS-Beplankung; 2-fach Gipsfaserplatten" | WI-GKF | 0 | A | 11.25 | 1263HWa0812800868 | NEW | no | no |  | 0 | no | 0 | no | Codetext
 | H2 Ebene +3 | WI-GKF | 1263Wa 0812800877 | yes | Codetext | m² | Trockenbauarbeiten | Wand | "BS-Beplankung; 2-fach Gipsfaserplatten" | WI-GKF | 0 | A | 11.25 | 1263HWa0812800870 | NEW | no | no |  | 0 | no | 0 | no | Codetext
 | H2 Ebene +3 | WI-GKF | 1263Wa 0812800876 | yes | Codetext | m² | Trockenbauarbeiten | Wand | "BS-Beplankung; 2-fach Gipsfaserplatten" | WI-GKF | 0 | A | 11.25 | 1263HWa0812800869 | NEW | no | no |  | 0 | no | 0 | no | Codetext
 | H2 Ebene +3 | WI-GKF | 1263Wa 0812799457 | yes | Codetext | m² | Trockenbauarbeiten | Wand | "BS-Beplankung; 2-fach Gipsfaserplatten" | WI-GKF | 0 | A | 11.25 | 1263HWa0812799450 | NEW | no | no |  | 0 | no | 0 | no | Codetext
 | H2 Ebene +3 | WI-GKF | 1263Wa 0812799458 | yes | Codetext | m² | Trockenbauarbeiten | Wand | "BS-Beplankung; 2-fach Gipsfaserplatten" | WI-GKF | 0 | A | 11.25 | 1263HWa0812799451 | NEW | no | no |  | 0 | no | 0 | no | Codetext
 | H2 Ebene +3 | WI-GKF | 1263Wa 0812799456 | yes | Codetext | m² | Trockenbauarbeiten | Wand | "BS-Beplankung; 2-fach Gipsfaserplatten" | WI-GKF | 0 | A | 11.25 | 1263HWa0812799449 | NEW | no | no |  | 0 | no | 0 | no | Codetext
 | H2 Ebene +3 | WI-GKF | 1263Wa 0812799459 | yes | Codetext | m² | Trockenbauarbeiten | Wand | "BS-Beplankung; 2-fach Gipsfaserplatten" | WI-GKF | 0 | A | 11.25 | 1263HWa0812799448 | NEW | no | no |  | 0 | no | 0 | no | Codetext
 | H2 Ebene +3 | WI-GKF | 1263Wa 0812799499 | yes | Codetext | m² | Trockenbauarbeiten | Wand | "BS-Beplankung; 2-fach Gipsfaserplatten" | WI-GKF | 0 | A | 11.25 | 1263HWa0812799488 | NEW | no | no |  | 0 | no | 0 | no | Codetext
 | H2 Ebene +3 | WI-GKF | 1263Wa 0812799498 | yes | Codetext | m² | Trockenbauarbeiten | Wand | "BS-Beplankung; 2-fach Gipsfaserplatten" | WI-GKF | 0 | A | 11.25 | 1263HWa0812799491 | NEW | no | no |  | 0 | no | 0 | no | Codetext
 | H2 Ebene +3 | WI-GKF | 1263Wa 0812799497 | yes | Codetext | m² | Trockenbauarbeiten | Wand | "BS-Beplankung; 2-fach Gipsfaserplatten" | WI-GKF | 0 | A | 11.25 | 1263HWa0812799490 | NEW | no | no |  | 0 | no | 0 | no | Codetext
 | H2 Ebene +3 | WI-GKF | 1263Wa 0812799496 | yes | Codetext | m² | Trockenbauarbeiten | Wand | "BS-Beplankung; 2-fach Gipsfaserplatten" | WI-GKF | 0 | A | 11.25 | 1263HWa0812799489 | NEW | no | no |  | 0 | no | 0 | no | Codetext
 | H2 Ebene +3 | WI-GKF | 1263Wa 0812800128 | yes | Codetext | m² | Trockenbauarbeiten | Wand | "BS-Beplankung; 2-fach Gipsfaserplatten" | WI-GKF | 0 | A | 11.25 | 1263HWa0812800121 | NEW | no | no |  | 0 | no | 0 | no | Codetext
 | H2 Ebene +3 | WI-GKF | 1263Wa 0812800130 | yes | Codetext | m² | Trockenbauarbeiten | Wand | "BS-Beplankung; 2-fach Gipsfaserplatten" | WI-GKF | 0 | A | 11.25 | 1263HWa0812800123 | NEW | no | no |  | 0 | no | 0 | no | Codetext
 | H2 Ebene +3 | WI-GKF | 1263Wa 0812800129 | yes | Codetext | m² | Trockenbauarbeiten | Wand | "BS-Beplankung; 2-fach Gipsfaserplatten" | WI-GKF | 0 | A | 11.25 | 1263HWa0812800122 | NEW | no | no |  | 0 | no | 0 | no | Codetext
 | H2 Ebene +3 | WI-GKF | 1263Wa 0812800131 | yes | Codetext | m² | Trockenbauarbeiten | Wand | "BS-Beplankung; 2-fach Gipsfaserplatten" | WI-GKF | 0 | A | 11.25 | 1263HWa0812800120 | NEW | no | no |  | 0 | no | 0 | no | Codetext
 | H2 Ebene +3 | WI-LB | 1263Wa 0813010392 | yes | Codetext | m² | Trockenbauarbeiten | Wand | Innenwand 1-Schalig | WI-LB | 0 | A | 11.25 | 1263HWa0812544490 | NEW |  | no | REI 60-A1 - D,s2-d0 +A1 | 0 | no | 0 | no | Codetext | AllplanAttributes - ash_W_Trockenbau_Qualitäten: 9
 | H2 Ebene +3 | WI-STB | 1263Wa 0812981769 | yes | Codetext | m² | Betonarbeiten | Wand | Innenwand 1-Schalig | WI-STB | 0 | A | 11.25 | 1263HWa0812544236 | NEW | yes | no | REI-M 60-A1 | 0 | no | 0 | no | Codetext | AllplanAttributes - ash D_Detailverweis: DT 3; ash D_Plannummer: D1615; Text1: SB3
 | H2 Ebene +3 | WI-STB | 1263Wa 0812981700 | yes | Codetext | m² | Betonarbeiten | Wand | Innenwand 1-Schalig | WI-STB | 0 | A | 11.25 | 1263HWa0812544236 | NEW | yes | no | REI-M 60-A1 | 0 | no | 0 | no | Codetext | AllplanAttributes - ash D_Detailverweis: DT 3; ash D_Plannummer: D1615; Text1: SB3
 | H2 Ebene +3 | WI-STB | 1263Wa 0813026241 | yes | Codetext | m² | Betonarbeiten | Wand | Innenwand 1-Schalig | WI-STB | 0 | A | 11.25 | 1263HWa0812544236 | NEW | yes | no | REI-M 60-A1 | 0 | no | 0 | no | Codetext | AllplanAttributes - ash D_Detailverweis: DT 3; ash D_Plannummer: D1615; Text1: SB3
 | H2 Ebene +3 | WI-STB | 1263Wa 0813026246 | yes | Codetext | m² | Betonarbeiten | Wand | Innenwand 1-Schalig | WI-STB | 0 | A | 11.25 | 1263HWa0812544236 | NEW | yes | no | REI-M 60-A1 | 0 | no | 0 | no | Codetext | AllplanAttributes - ash D_Detailverweis: DT 3; ash D_Plannummer: D1615; Text1: SB3
 | H2 Ebene +3 | WI-STB | 1263Wa 0813026213 | yes | Codetext | m² | Betonarbeiten | Wand | Innenwand 1-Schalig | WI-STB | 0 | A | 11.25 | 1263HWa0812544236 | NEW | yes | no | REI-M 60-A1 | 0 | no | 0 | no | Codetext | AllplanAttributes - ash D_Detailverweis: DT 3; ash D_Plannummer: D1615; Text1: SB3
 | H2 Ebene +3 | WI-STB | 1263Wa 0813026218 | yes | Codetext | m² | Betonarbeiten | Wand | Innenwand 1-Schalig | WI-STB | 0 | A | 11.25 | 1263HWa0812544236 | NEW | yes | no | REI-M 60-A1 | 0 | no | 0 | no | Codetext | AllplanAttributes - ash D_Detailverweis: DT 3; ash D_Plannummer: D1615; Text1: SB3
 | H2 Ebene +3 | WI-GKF | 1263Wa 0813030518 | yes | Codetext | m² | Trockenbauarbeiten | Wand | "BS-Beplankung; 2-fach Gipsfaserplatten" | WI-GKF | 0 | A | 11.25 | 1263HWa0812799429 | NEW | no | no |  | 0 | no | 0 | no | Codetext
 | H2 Ebene +3 | WI-GKF | 1263Wa 0813030520 | yes | Codetext | m² | Trockenbauarbeiten | Wand | "BS-Beplankung; 2-fach Gipsfaserplatten" | WI-GKF | 0 | A | 11.25 | 1263HWa0812799428 | NEW | no | no |  | 0 | no | 0 | no | Codetext
 | H2 Ebene +3 | WI-GKF | 1263Wa 0813030524 | yes | Codetext | m² | Trockenbauarbeiten | Wand | "BS-Beplankung; 2-fach Gipsfaserplatten" | WI-GKF | 0 | A | 11.25 | 1263HWa0812799431 | NEW | no | no |  | 0 | no | 0 | no | Codetext
 | H2 Ebene +3 | WI-GKF | 1263Wa 0813030522 | yes | Codetext | m² | Trockenbauarbeiten | Wand | "BS-Beplankung; 2-fach Gipsfaserplatten" | WI-GKF | 0 | A | 11.25 | 1263HWa0812799430 | NEW | no | no |  | 0 | no | 0 | no | Codetext
 | H2 Ebene +3 | WI-GKF | 1263Wa 0812799621 | yes | Codetext | m² | Trockenbauarbeiten | Wand | "BS-Beplankung; 2-fach Gipsfaserplatten" | WI-GKF | 0 | A | 11.25 | 1263HWa0812799615 | NEW | no | no |  | 0 | no | 0 | no | Codetext
 | H2 Ebene +3 | WI-GKF | 1263Wa 0813034839 | yes | Codetext | m² | Trockenbauarbeiten | Wand | "BS-Beplankung; 2-fach Gipsfaserplatten" | WI-GKF | 0 | A | 11.25 | 1263HWa0812799429 | NEW | no | no |  | 0 | no | 0 | no | Codetext
 | H2 Ebene +3 | WI-GKF | 1263Wa 0813034841 | yes | Codetext | m² | Trockenbauarbeiten | Wand | "BS-Beplankung; 2-fach Gipsfaserplatten" | WI-GKF | 0 | A | 11.25 | 1263HWa0812799431 | NEW | no | no |  | 0 | no | 0 | no | Codetext
 | H2 Ebene +3 | WI-GKF | 1263Wa 0813034845 | yes | Codetext | m² | Trockenbauarbeiten | Wand | "BS-Beplankung; 2-fach Gipsfaserplatten" | WI-GKF | 0 | A | 11.25 | 1263HWa0812799430 | NEW | no | no |  | 0 | no | 0 | no | Codetext
 | H2 Ebene +3 | WI-GKF | 1263Wa 0813034843 | yes | Codetext | m² | Trockenbauarbeiten | Wand | "BS-Beplankung; 2-fach Gipsfaserplatten" | WI-GKF | 0 | A | 11.25 | 1263HWa0812799428 | NEW | no | no |  | 0 | no | 0 | no | Codetext
 | H2 Ebene +3 | WI-GKF | 1263Wa 0813034853 | yes | Codetext | m² | Trockenbauarbeiten | Wand | "BS-Beplankung; 2-fach Gipsfaserplatten" | WI-GKF | 0 | A | 11.25 | 1263HWa0812799429 | NEW | no | no |  | 0 | no | 0 | no | Codetext
 | H2 Ebene +3 | WI-GKF | 1263Wa 0813034859 | yes | Codetext | m² | Trockenbauarbeiten | Wand | "BS-Beplankung; 2-fach Gipsfaserplatten" | WI-GKF | 0 | A | 11.25 | 1263HWa0812799428 | NEW | no | no |  | 0 | no | 0 | no | Codetext
 | H2 Ebene +3 | WI-GKF | 1263Wa 0813034857 | yes | Codetext | m² | Trockenbauarbeiten | Wand | "BS-Beplankung; 2-fach Gipsfaserplatten" | WI-GKF | 0 | A | 11.25 | 1263HWa0812799431 | NEW | no | no |  | 0 | no | 0 | no | Codetext
 | H2 Ebene +3 | WI-GKF | 1263Wa 0813034847 | yes | Codetext | m² | Trockenbauarbeiten | Wand | "BS-Beplankung; 2-fach Gipsfaserplatten" | WI-GKF | 0 | A | 11.25 | 1263HWa0812799430 | NEW | no | no |  | 0 | no | 0 | no | Codetext
 | H2 Ebene +3 | WI-GKF | 1263Wa 0813034861 | yes | Codetext | m² | Trockenbauarbeiten | Wand | "BS-Beplankung; 2-fach Gipsfaserplatten" | WI-GKF | 0 | A | 11.25 | 1263HWa0812799429 | NEW | no | no |  | 0 | no | 0 | no | Codetext
 | H2 Ebene +3 | WI-GKF | 1263Wa 0813034867 | yes | Codetext | m² | Trockenbauarbeiten | Wand | "BS-Beplankung; 2-fach Gipsfaserplatten" | WI-GKF | 0 | A | 11.25 | 1263HWa0812799428 | NEW | no | no |  | 0 | no | 0 | no | Codetext
 | H2 Ebene +3 | WI-GKF | 1263Wa 0813034865 | yes | Codetext | m² | Trockenbauarbeiten | Wand | "BS-Beplankung; 2-fach Gipsfaserplatten" | WI-GKF | 0 | A | 11.25 | 1263HWa0812799431 | NEW | no | no |  | 0 | no | 0 | no | Codetext
 | H2 Ebene +3 | WI-GKF | 1263Wa 0813034849 | yes | Codetext | m² | Trockenbauarbeiten | Wand | "BS-Beplankung; 2-fach Gipsfaserplatten" | WI-GKF | 0 | A | 11.25 | 1263HWa0812799430 | NEW | no | no |  | 0 | no | 0 | no | Codetext
 | H2 Ebene +3 | WI-GKF | 1263Wa 0813034869 | yes | Codetext | m² | Trockenbauarbeiten | Wand | "BS-Beplankung; 2-fach Gipsfaserplatten" | WI-GKF | 0 | A | 11.25 | 1263HWa0812799429 | NEW | no | no |  | 0 | no | 0 | no | Codetext
 | H2 Ebene +3 | WI-GKF | 1263Wa 0813034875 | yes | Codetext | m² | Trockenbauarbeiten | Wand | "BS-Beplankung; 2-fach Gipsfaserplatten" | WI-GKF | 0 | A | 11.25 | 1263HWa0812799428 | NEW | no | no |  | 0 | no | 0 | no | Codetext
 | H2 Ebene +3 | WI-GKF | 1263Wa 0813034873 | yes | Codetext | m² | Trockenbauarbeiten | Wand | "BS-Beplankung; 2-fach Gipsfaserplatten" | WI-GKF | 0 | A | 11.25 | 1263HWa0812799431 | NEW | no | no |  | 0 | no | 0 | no | Codetext
 | H2 Ebene +3 | WI-GKF | 1263Wa 0813034851 | yes | Codetext | m² | Trockenbauarbeiten | Wand | "BS-Beplankung; 2-fach Gipsfaserplatten" | WI-GKF | 0 | A | 11.25 | 1263HWa0812799430 | NEW | no | no |  | 0 | no | 0 | no | Codetext
 | H2 Ebene +3 | WI-LB | 1263Wa 0812546431 | yes | Codetext | m² | Trockenbauarbeiten | Wand | Innenwand 1-Schalig | WI-LB | 0 | A | 11.25 | 1263HWa0812544150 | NEW | no | no | REI 60-A1 - A2,s1-d0 / A1 | 0 | no | 0 | no | Codetext | AllplanAttributes - Ortscode_Geschoßbezeichnung: E03; W_Deckenanschluss: Gleitender Deckenanschluss Fall 01; ash_W_Trockenbau_Qualitäten: 1b
 | H2 Ebene +3 | WI-LB | 1263Wa 0812799740 | yes | Codetext | m² | Trockenbauarbeiten | Wand | Innenwand 1-Schalig | WI-LB | 0 | A | 11.25 | 1263HWa0812799737 | NEW | no | no | REI 60-A1 - A2,s1-d0 / A1 | 0 | no | 0 | no | Codetext | AllplanAttributes - Ortscode_Geschoßbezeichnung: E03; W_Deckenanschluss: Gleitender Deckenanschluss Fall 01; ash_W_Trockenbau_Qualitäten: 1b
 | H2 Ebene +3 | WI-GKF | 1263Wa 0813030746 | yes | Codetext | m² | Trockenbauarbeiten | Wand | "BS-Beplankung; 2-fach Gipsfaserplatten" | WI-GKF | 0 | A | 11.25 | 1263HWa0812799429 | NEW | no | no |  | 0 | no | 0 | no | Codetext
 | H2 Ebene +3 | WI-GKF | 1263Wa 0813030739 | yes | Codetext | m² | Trockenbauarbeiten | Wand | "BS-Beplankung; 2-fach Gipsfaserplatten" | WI-GKF | 0 | A | 11.25 | 1263HWa0812799428 | NEW | no | no |  | 0 | no | 0 | no | Codetext
 | H2 Ebene +3 | WI-GKF | 1263Wa 0813030740 | yes | Codetext | m² | Trockenbauarbeiten | Wand | "BS-Beplankung; 2-fach Gipsfaserplatten" | WI-GKF | 0 | A | 11.25 | 1263HWa0812799431 | NEW | no | no |  | 0 | no | 0 | no | Codetext
 | H2 Ebene +3 | WI-GKF | 1263Wa 0813030742 | yes | Codetext | m² | Trockenbauarbeiten | Wand | "BS-Beplankung; 2-fach Gipsfaserplatten" | WI-GKF | 0 | A | 11.25 | 1263HWa0812799430 | NEW | no | no |  | 0 | no | 0 | no | Codetext
 | H2 Ebene +3 | WI-GKF | 1263Wa 0813030709 | yes | Codetext | m² | Trockenbauarbeiten | Wand | "BS-Beplankung; 2-fach Gipsfaserplatten" | WI-GKF | 0 | A | 11.25 | 1263HWa0812799429 | NEW | no | no |  | 0 | no | 0 | no | Codetext
 | H2 Ebene +3 | WI-GKF | 1263Wa 0813030702 | yes | Codetext | m² | Trockenbauarbeiten | Wand | "BS-Beplankung; 2-fach Gipsfaserplatten" | WI-GKF | 0 | A | 11.25 | 1263HWa0812799428 | NEW | no | no |  | 0 | no | 0 | no | Codetext
 | H2 Ebene +3 | WI-GKF | 1263Wa 0813030703 | yes | Codetext | m² | Trockenbauarbeiten | Wand | "BS-Beplankung; 2-fach Gipsfaserplatten" | WI-GKF | 0 | A | 11.25 | 1263HWa0812799431 | NEW | no | no |  | 0 | no | 0 | no | Codetext
 | H2 Ebene +3 | WI-GKF | 1263Wa 0813030705 | yes | Codetext | m² | Trockenbauarbeiten | Wand | "BS-Beplankung; 2-fach Gipsfaserplatten" | WI-GKF | 0 | A | 11.25 | 1263HWa0812799430 | NEW | no | no |  | 0 | no | 0 | no | Codetext
 | H2 Ebene +3 | WI-GKF | 1263Wa 0812799437 | yes | Codetext | m² | Trockenbauarbeiten | Wand | "BS-Beplankung; 2-fach Gipsfaserplatten" | WI-GKF | 0 | A | 11.25 | 1263HWa0812799431 | NEW | no | no |  | 0 | no | 0 | no | Codetext
 | H2 Ebene +3 | WI-GKF | 1263Wa 0812799439 | yes | Codetext | m² | Trockenbauarbeiten | Wand | "BS-Beplankung; 2-fach Gipsfaserplatten" | WI-GKF | 0 | A | 11.25 | 1263HWa0812799429 | NEW | no | no |  | 0 | no | 0 | no | Codetext
 | H2 Ebene +3 | WI-GKF | 1263Wa 0812799436 | yes | Codetext | m² | Trockenbauarbeiten | Wand | "BS-Beplankung; 2-fach Gipsfaserplatten" | WI-GKF | 0 | A | 11.25 | 1263HWa0812799428 | NEW | no | no |  | 0 | no | 0 | no | Codetext
 | H2 Ebene +3 | WI-GKF | 1263Wa 0812799438 | yes | Codetext | m² | Trockenbauarbeiten | Wand | "BS-Beplankung; 2-fach Gipsfaserplatten" | WI-GKF | 0 | A | 11.25 | 1263HWa0812799430 | NEW | no | no |  | 0 | no | 0 | no | Codetext
 | H2 Ebene +3 | WI-GKF | 1263Wa 0812799416 | yes | Codetext | m² | Trockenbauarbeiten | Wand | "BS-Beplankung; 2-fach Gipsfaserplatten" | WI-GKF | 0 | A | 11.25 | 1263HWa0812799409 | NEW | no | no |  | 0 | no | 0 | no | Codetext
 | H2 Ebene +3 | WI-GKF | 1263Wa 0812799419 | yes | Codetext | m² | Trockenbauarbeiten | Wand | "BS-Beplankung; 2-fach Gipsfaserplatten" | WI-GKF | 0 | A | 11.25 | 1263HWa0812799408 | NEW | no | no |  | 0 | no | 0 | no | Codetext
 | H2 Ebene +3 | WI-GKF | 1263Wa 0812799418 | yes | Codetext | m² | Trockenbauarbeiten | Wand | "BS-Beplankung; 2-fach Gipsfaserplatten" | WI-GKF | 0 | A | 11.25 | 1263HWa0812799411 | NEW | no | no |  | 0 | no | 0 | no | Codetext
 | H2 Ebene +3 | WI-GKF | 1263Wa 0812799417 | yes | Codetext | m² | Trockenbauarbeiten | Wand | "BS-Beplankung; 2-fach Gipsfaserplatten" | WI-GKF | 0 | A | 11.25 | 1263HWa0812799410 | NEW | no | no |  | 0 | no | 0 | no | Codetext
 | H2 Ebene +3 | WI-GKF | 1263Wa 0812799397 | yes | Codetext | m² | Trockenbauarbeiten | Wand | "BS-Beplankung; 2-fach Gipsfaserplatten" | WI-GKF | 0 | A | 11.25 | 1263HWa0812799391 | NEW | no | no |  | 0 | no | 0 | no | Codetext
 | H2 Ebene +3 | WI-GKF | 1263Wa 0812799398 | yes | Codetext | m² | Trockenbauarbeiten | Wand | "BS-Beplankung; 2-fach Gipsfaserplatten" | WI-GKF | 0 | A | 11.25 | 1263HWa0812799390 | NEW | no | no |  | 0 | no | 0 | no | Codetext
 | H2 Ebene +3 | WI-GKF | 1263Wa 0812799399 | yes | Codetext | m² | Trockenbauarbeiten | Wand | "BS-Beplankung; 2-fach Gipsfaserplatten" | WI-GKF | 0 | A | 11.25 | 1263HWa0812799389 | NEW | no | no |  | 0 | no | 0 | no | Codetext
 | H2 Ebene +3 | WI-GKF | 1263Wa 0812799396 | yes | Codetext | m² | Trockenbauarbeiten | Wand | "BS-Beplankung; 2-fach Gipsfaserplatten" | WI-GKF | 0 | A | 11.25 | 1263HWa0812799388 | NEW | no | no |  | 0 | no | 0 | no | Codetext
 | H2 Ebene +3 | WI-GKF | 1263Wa 0812799359 | yes | Codetext | m² | Trockenbauarbeiten | Wand | "BS-Beplankung; 2-fach Gipsfaserplatten" | WI-GKF | 0 | A | 11.25 | 1263HWa0812799348 | NEW | no | no |  | 0 | no | 0 | no | Codetext
 | H2 Ebene +3 | WI-GKF | 1263Wa 0812799358 | yes | Codetext | m² | Trockenbauarbeiten | Wand | "BS-Beplankung; 2-fach Gipsfaserplatten" | WI-GKF | 0 | A | 11.25 | 1263HWa0812799351 | NEW | no | no |  | 0 | no | 0 | no | Codetext
 | H2 Ebene +3 | WI-GKF | 1263Wa 0812799356 | yes | Codetext | m² | Trockenbauarbeiten | Wand | "BS-Beplankung; 2-fach Gipsfaserplatten" | WI-GKF | 0 | A | 11.25 | 1263HWa0812799349 | NEW | no | no |  | 0 | no | 0 | no | Codetext
 | H2 Ebene +3 | WI-GKF | 1263Wa 0812799357 | yes | Codetext | m² | Trockenbauarbeiten | Wand | "BS-Beplankung; 2-fach Gipsfaserplatten" | WI-GKF | 0 | A | 11.25 | 1263HWa0812799350 | NEW | no | no |  | 0 | no | 0 | no | Codetext
 | H2 Ebene +3 | WI-GKF | 1263Wa 0813030783 | yes | Codetext | m² | Trockenbauarbeiten | Wand | "BS-Beplankung; 2-fach Gipsfaserplatten" | WI-GKF | 0 | A | 11.25 | 1263HWa0812799429 | NEW | no | no |  | 0 | no | 0 | no | Codetext
 | H2 Ebene +3 | WI-GKF | 1263Wa 0813030777 | yes | Codetext | m² | Trockenbauarbeiten | Wand | "BS-Beplankung; 2-fach Gipsfaserplatten" | WI-GKF | 0 | A | 11.25 | 1263HWa0812799431 | NEW | no | no |  | 0 | no | 0 | no | Codetext
 | H2 Ebene +3 | WI-GKF | 1263Wa 0813030779 | yes | Codetext | m² | Trockenbauarbeiten | Wand | "BS-Beplankung; 2-fach Gipsfaserplatten" | WI-GKF | 0 | A | 11.25 | 1263HWa0812799430 | NEW | no | no |  | 0 | no | 0 | no | Codetext
 | H2 Ebene +3 | WI-GKF | 1263Wa 0813030776 | yes | Codetext | m² | Trockenbauarbeiten | Wand | "BS-Beplankung; 2-fach Gipsfaserplatten" | WI-GKF | 0 | A | 11.25 | 1263HWa0812799428 | NEW | no | no |  | 0 | no | 0 | no | Codetext
 | H2 Ebene +3 | WI-GKF | 1263Wa 0812799478 | yes | Codetext | m² | Trockenbauarbeiten | Wand | "BS-Beplankung; 2-fach Gipsfaserplatten" | WI-GKF | 0 | A | 11.25 | 1263HWa0812799470 | NEW | no | no |  | 0 | no | 0 | no | Codetext
 | H2 Ebene +3 | WI-GKF | 1263Wa 0812799476 | yes | Codetext | m² | Trockenbauarbeiten | Wand | "BS-Beplankung; 2-fach Gipsfaserplatten" | WI-GKF | 0 | A | 11.25 | 1263HWa0812799468 | NEW | no | no |  | 0 | no | 0 | no | Codetext
 | H2 Ebene +3 | WI-GKF | 1263Wa 0812799479 | yes | Codetext | m² | Trockenbauarbeiten | Wand | "BS-Beplankung; 2-fach Gipsfaserplatten" | WI-GKF | 0 | A | 11.25 | 1263HWa0812799469 | NEW | no | no |  | 0 | no | 0 | no | Codetext
 | H2 Ebene +3 | WI-GKF | 1263Wa 0812799477 | yes | Codetext | m² | Trockenbauarbeiten | Wand | "BS-Beplankung; 2-fach Gipsfaserplatten" | WI-GKF | 0 | A | 11.25 | 1263HWa0812799471 | NEW | no | no |  | 0 | no | 0 | no | Codetext
 | H2 Ebene +3 | WI-GKF | 1263Wa 0812799558 | yes | Codetext | m² | Trockenbauarbeiten | Wand | "BS-Beplankung; 2-fach Gipsfaserplatten" | WI-GKF | 0 | A | 11.25 | 1263HWa0812799550 | NEW | no | no |  | 0 | no | 0 | no | Codetext
 | H2 Ebene +3 | WI-GKF | 1263Wa 0812799557 | yes | Codetext | m² | Trockenbauarbeiten | Wand | "BS-Beplankung; 2-fach Gipsfaserplatten" | WI-GKF | 0 | A | 11.25 | 1263HWa0812799551 | NEW | no | no |  | 0 | no | 0 | no | Codetext
 | H2 Ebene +3 | WI-GKF | 1263Wa 0812799559 | yes | Codetext | m² | Trockenbauarbeiten | Wand | "BS-Beplankung; 2-fach Gipsfaserplatten" | WI-GKF | 0 | A | 11.25 | 1263HWa0812799549 | NEW | no | no |  | 0 | no | 0 | no | Codetext
 | H2 Ebene +3 | WI-GKF | 1263Wa 0812799556 | yes | Codetext | m² | Trockenbauarbeiten | Wand | "BS-Beplankung; 2-fach Gipsfaserplatten" | WI-GKF | 0 | A | 11.25 | 1263HWa0812799548 | NEW | no | no |  | 0 | no | 0 | no | Codetext
 | H2 Ebene +3 | WI-GKF | 1263Wa 0812799518 | yes | Codetext | m² | Trockenbauarbeiten | Wand | "BS-Beplankung; 2-fach Gipsfaserplatten" | WI-GKF | 0 | A | 11.25 | 1263HWa0812799510 | NEW | no | no |  | 0 | no | 0 | no | Codetext
 | H2 Ebene +3 | WI-GKF | 1263Wa 0812799516 | yes | Codetext | m² | Trockenbauarbeiten | Wand | "BS-Beplankung; 2-fach Gipsfaserplatten" | WI-GKF | 0 | A | 11.25 | 1263HWa0812799508 | NEW | no | no |  | 0 | no | 0 | no | Codetext
 | H2 Ebene +3 | WI-GKF | 1263Wa 0812799519 | yes | Codetext | m² | Trockenbauarbeiten | Wand | "BS-Beplankung; 2-fach Gipsfaserplatten" | WI-GKF | 0 | A | 11.25 | 1263HWa0812799509 | NEW | no | no |  | 0 | no | 0 | no | Codetext
 | H2 Ebene +3 | WI-GKF | 1263Wa 0812799517 | yes | Codetext | m² | Trockenbauarbeiten | Wand | "BS-Beplankung; 2-fach Gipsfaserplatten" | WI-GKF | 0 | A | 11.25 | 1263HWa0812799511 | NEW | no | no |  | 0 | no | 0 | no | Codetext
 | H2 Ebene +3 | WI-LB | 1263Wa 0813017071 | yes | Codetext | m² | Trockenbauarbeiten | Wand | Innenwand 1-Schalig | WI-LB | 0 | A | 11.25 | 1263HWa0812544148 | NEW | no | no | REI 60-A1 - A2,s1-d0 / A1 | 0 | no | 0 | no | Codetext | AllplanAttributes - W_Deckenanschluss: Gleitender Deckenanschluss Fall 01; ash_W_Trockenbau_Qualitäten: 1b
 | H2 Ebene +3 | WI-STB | 1263Wa 0813064860 | yes | Codetext | m² | Betonarbeiten | Wand | Innenwand 1-Schalig | WI-STB | 0 | A | 11.25 | 1263HWa0812544977 | NEW | yes | no | REI 60-A1 - A2,s1-d0 / A1 | 0 | no | 0 | no | Codetext
 | H2 Ebene +3 | WI-LB | 1263Wa 0813064862 | yes | Codetext | m² | Trockenbauarbeiten | Wand | Innenwand 1-Schalig | WI-LB | 0 | A | 7.5 | 1213HWa0812969822 | NEW | no | no | REI 60-A1 - D,s2-d0 /A1 | 0 | no | 0 | no | Codetext | AllplanAttributes - ash_W_Trockenbau_Qualitäten: 16
 | H2 Ebene +3 | WI-LB | 1263Wa 0812786487 | yes | Codetext | m² | Trockenbauarbeiten | Wand | Innenwand 1-Schalig | WI-LB | 0 | A | 11.25 | 1263HWa0812786486 | NEW | no | no | REI 60-A1 - A2,s1-d0 / A1 | 0 | no | 42 | no | Codetext | AllplanAttributes - W_Deckenanschluss: Gleitender Deckenanschluss Fall 01; ash_W_Trockenbau_Qualitäten: 13
 | H2 Ebene +3 | WI-LB | 1263Wa 0813025632 | yes | Codetext | m² | Trockenbauarbeiten | Wand | Innenwand 1-Schalig | WI-LB | 0 | A | 11.25 | 1263HWa0812786486 | NEW | no | no | REI 60-A1 - A2,s1-d0 / A1 | 0 | no | 42 | no | Codetext | AllplanAttributes - W_Deckenanschluss: Gleitender Deckenanschluss Fall 01; ash_W_Trockenbau_Qualitäten: 13
 | H2 Ebene +3 | WI-LB | 1263Wa 0812906747 | yes | Codetext | m² | Trockenbauarbeiten | Wand | Innenwand 1-Schalig | WI-LB | 0 | A | 11.25 | 1263HWa0812906742 | NEW | no | no | REI 60-A1 - D,s2-d0 +A1 | 0 | no | 0 | no | Codetext | AllplanAttributes - W_Deckenanschluss: Gleitender Deckenanschluss Fall 01; ash_W_Trockenbau_Qualitäten: 12b
 | H2 Ebene +2 | WA-LB | 1205Wa 0000180436 | yes |  | m² | Trockenbauarbeiten | Wand | Außenwand 7-Schalig | WA-LB |  |  | 7.5 | 1205HWa0000180435 | NEW |  | yes | 0 | 0.9 |  | 32 | AllplanAttributes - ash D_Detailverweis: <undefiniert>; Sicherheitsklasse: -; Sonnenschutztyp: Movable; g-Wert: 0,51
 | H2 Ebene +2 | WA-LB | 1205Wa 0000183006 | yes | Codetext | m² | Trockenbauarbeiten | Wand | Außenwand 7-Schalig | WA-LB | 0 | A | 7.5 | 1205HWa0000183005 | NEW |  | yes | 0 | 0.9 | no | 32 | no | Codetext | AllplanAttributes - ash D_Detailverweis: <undefiniert>; Sicherheitsklasse: -; Sonnenschutztyp: Movable; g-Wert: 0,51
 | H2 Ebene +2 | WI-STB | 1205Wa 0000252754 | yes | Codetext | m² | Zimmer- und Holzbauarbeiten | Wand | Außenwand 7-Schalig | WI-STB | 0 | A | 7.5 | 1213HWa0812968545 | NEW | yes | no | REI 60-A1 - D,s2-d0 /A1 | 0 | no | 0 | no | Codetext | AllplanAttributes - Ortscode_Geschoßbezeichnung: E02; ash D_Detailverweis: <undefiniert>
 | H2 Ebene +2 | WI-STB | 1205Wa 0000252755 | yes | Codetext | m² | Zimmer- und Holzbauarbeiten | Wand | Außenwand 7-Schalig | WI-STB | 0 | A | 7.5 | 1213HWa0812968545 | NEW | yes | no | REI 60-A1 - D,s2-d0 /A1 | 0 | no | 0 | no | Codetext | AllplanAttributes - Ortscode_Geschoßbezeichnung: E02; ash D_Detailverweis: <undefiniert>
 | H2 Ebene +2 | WA-LB | 1205Wa 0000003844 | yes | Codetext | m² | Trockenbauarbeiten | Wand | Außenwand 7-Schalig | WA-LB | 0 | A | 7.5 | 1205HWa0000003166 | NEW | no | yes | 0 | 0.9 | no | 32 | no | Codetext | AllplanAttributes - ash D_Detailverweis: <undefiniert>; Sicherheitsklasse: -; Sonnenschutztyp: Movable; g-Wert: 0,51
 | H2 Ebene +2 | WA-DL | 1205Wa 0000003834 | yes | Codetext | m³ | Zimmer- und Holzbauarbeiten | Wand | Außenwand 7-Schalig | WA-DL | 0 | A | 7.5 | 1205HWa0000003166 | NEW | no | yes | 0 | 0.9 | no | 32 | no | Codetext | AllplanAttributes - ash D_Detailverweis: DT D; ash D_Plannummer: D1851; Sicherheitsklasse: -; Sonnenschutztyp: Movable; g-Wert: 0,51; ash W_laufende Nr. Statik: 2 (W 2.0/ 2.1/ 2.2)
 | H2 Ebene +2 | WA-DL | 1205Wa 0000003824 | yes | Codetext | m³ | Zimmer- und Holzbauarbeiten | Wand | Außenwand 7-Schalig | WA-DL | 0 | A | 7.5 | 1205HWa0000003166 | NEW | no | yes | 0 | 0.9 | no | 32 | no | Codetext | AllplanAttributes - ash D_Detailverweis: <undefiniert>; Sicherheitsklasse: -; Sonnenschutztyp: Movable; g-Wert: 0,51
 | H2 Ebene +2 | WA-LB | 1205Wa 0000003814 | yes | Codetext | m² | Trockenbauarbeiten | Wand | Außenwand 7-Schalig | WA-LB | 0 | A | 7.5 | 1205HWa0000003166 | NEW | no | yes | 0 | 0.9 | no | 32 | no | Codetext | AllplanAttributes - ash D_Detailverweis: <undefiniert>; Sicherheitsklasse: -; Sonnenschutztyp: Movable; g-Wert: 0,51
 | H2 Ebene +2 | WA-KL | 1205Wa 0000003804 | yes | Codetext | m² | Zimmer- und Holzbauarbeiten | Wand | Außenwand 7-Schalig | WA-KL | 0 | A | 7.5 | 1205HWa0000003166 | NEW | no | yes | 0 | 0.9 | no | 32 | no | Codetext | AllplanAttributes - ash D_Detailverweis: <undefiniert>; Sicherheitsklasse: -; Sonnenschutztyp: Movable; g-Wert: 0,51
 | H2 Ebene +2 | WA-TL | 1205Wa 0000003794 | yes | Codetext | m² | Zimmer- und Holzbauarbeiten | Wand | Außenwand 7-Schalig | WA-TL | 0 | A | 7.5 | 1205HWa0000003166 | NEW | no | yes | 0 | 0.9 | no | 32 | no | Codetext | AllplanAttributes - ash D_Detailverweis: <undefiniert>; Sicherheitsklasse: -; Sonnenschutztyp: Movable; g-Wert: 0,51
 | H2 Ebene +2 | WA-HS | 1205Wa 0000003784 | yes | Codetext | m² | Zimmer- und Holzbauarbeiten | Wand | Außenwand 7-Schalig | WA-HS | 0 | A | 7.5 | 1205HWa0000003166 | NEW | no | yes | 0 | 0.9 | no | 32 | no | Codetext | AllplanAttributes - ash D_Detailverweis: <undefiniert>; Sicherheitsklasse: -; Sonnenschutztyp: Movable; g-Wert: 0,51
 | H2 Ebene +2 | WA-LB | 1205Wa 0000001868 | yes | Codetext | m² | Trockenbauarbeiten | Wand | Außenwand 7-Schalig | WA-LB | 0 | A | 7.5 | 1205HWa0000000198 | NEW | no | yes | 0 | 0.9 | no | 32 | no | Codetext | AllplanAttributes - ash D_Detailverweis: <undefiniert>; Sicherheitsklasse: -; Sonnenschutztyp: Movable; g-Wert: 0,51
 | H2 Ebene +2 | WA-HD | 1205Wa 0000001872 | yes | Codetext | m³ | Zimmer- und Holzbauarbeiten | Wand | Außenwand 7-Schalig | WA-HD | 0 | A | 7.5 | 1205HWa0000000198 | NEW | no | yes | 0 | 0.9 | no | 32 | no | Codetext | AllplanAttributes - ash D_Detailverweis: DT C; ash D_Plannummer: D1851; Sicherheitsklasse: -; Sonnenschutztyp: Movable; g-Wert: 0,51; ash W_laufende Nr. Statik: 2 (W 2.0/ 2.1/ 2.2)
 | H2 Ebene +2 | WA-DL | 1205Wa 0000001876 | yes | Codetext | m³ | Zimmer- und Holzbauarbeiten | Wand | Außenwand 7-Schalig | WA-DL | 0 | A | 7.5 | 1205HWa0000000198 | NEW | no | yes | 0 | 0.9 | no | 32 | no | Codetext | AllplanAttributes - ash D_Detailverweis: <undefiniert>; Sicherheitsklasse: -; Sonnenschutztyp: Movable; g-Wert: 0,51
 | H2 Ebene +2 | WA-LB | 1205Wa 0000001880 | yes | Codetext | m² | Trockenbauarbeiten | Wand | Außenwand 7-Schalig | WA-LB | 0 | A | 7.5 | 1205HWa0000000198 | NEW | no | yes | 0 | 0.9 | no | 32 | no | Codetext | AllplanAttributes - ash D_Detailverweis: <undefiniert>; Sicherheitsklasse: -; Sonnenschutztyp: Movable; g-Wert: 0,51
 | H2 Ebene +2 | WA-KL | 1205Wa 0000001884 | yes | Codetext | m² | Zimmer- und Holzbauarbeiten | Wand | Außenwand 7-Schalig | WA-KL | 0 | A | 7.5 | 1205HWa0000000198 | NEW | no | yes | 0 | 0.9 | no | 32 | no | Codetext | AllplanAttributes - ash D_Detailverweis: <undefiniert>; Sicherheitsklasse: -; Sonnenschutztyp: Movable; g-Wert: 0,51
 | H2 Ebene +2 | WA-TL | 1205Wa 0000001888 | yes | Codetext | m² | Zimmer- und Holzbauarbeiten | Wand | Außenwand 7-Schalig | WA-TL | 0 | A | 7.5 | 1205HWa0000000198 | NEW | no | yes | 0 | 0.9 | no | 32 | no | Codetext | AllplanAttributes - ash D_Detailverweis: <undefiniert>; Sicherheitsklasse: -; Sonnenschutztyp: Movable; g-Wert: 0,51
 | H2 Ebene +2 | WA-HS | 1205Wa 0000001892 | yes | Codetext | m² | Zimmer- und Holzbauarbeiten | Wand | Außenwand 7-Schalig | WA-HS | 0 | A | 7.5 | 1205HWa0000000198 | NEW | no | yes | 0 | 0.9 | no | 32 | no | Codetext | AllplanAttributes - ash D_Detailverweis: <undefiniert>; Sicherheitsklasse: -; Sonnenschutztyp: Movable; g-Wert: 0,51
 | H2 Ebene +2 | WA-LB | 1205Wa 0000001277 | yes | Codetext | m² | Trockenbauarbeiten | Wand | Außenwand 7-Schalig | WA-LB | 0 | A | 7.5 | 1205HWa0000000029 | NEW | no | yes | 0 | 0.9 | no | 32 | no | Codetext | AllplanAttributes - ash D_Detailverweis: <undefiniert>; Sicherheitsklasse: -; Sonnenschutztyp: Movable; g-Wert: 0,51
 | H2 Ebene +2 | WA-HD | 1205Wa 0000001301 | yes | Codetext | m³ | Zimmer- und Holzbauarbeiten | Wand | Außenwand 7-Schalig | WA-HD | 0 | A | 7.5 | 1205HWa0000000029 | NEW | no | yes | 0 | 0.9 | no | 32 | no | Codetext | AllplanAttributes - ash D_Detailverweis: <undefiniert>; Sicherheitsklasse: -; Sonnenschutztyp: Movable; g-Wert: 0,51; ash W_laufende Nr. Statik: 5 (W 4.0)
 | H2 Ebene +2 | WA-DL | 1205Wa 0000001303 | yes | Codetext | m³ | Zimmer- und Holzbauarbeiten | Wand | Außenwand 7-Schalig | WA-DL | 0 | A | 7.5 | 1205HWa0000000029 | NEW | no | yes | 0 | 0.9 | no | 32 | no | Codetext | AllplanAttributes - ash D_Detailverweis: <undefiniert>; Sicherheitsklasse: -; Sonnenschutztyp: Movable; g-Wert: 0,51
 | H2 Ebene +2 | WA-LB | 1205Wa 0000001305 | yes | Codetext | m² | Trockenbauarbeiten | Wand | Außenwand 7-Schalig | WA-LB | 0 | A | 7.5 | 1205HWa0000000029 | NEW | no | yes | 0 | 0.9 | no | 32 | no | Codetext | AllplanAttributes - ash D_Detailverweis: <undefiniert>; Sicherheitsklasse: -; Sonnenschutztyp: Movable; g-Wert: 0,51
 | H2 Ebene +2 | WA-KL | 1205Wa 0000001307 | yes | Codetext | m² | Zimmer- und Holzbauarbeiten | Wand | Außenwand 7-Schalig | WA-KL | 0 | A | 7.5 | 1205HWa0000000029 | NEW | no | yes | 0 | 0.9 | no | 32 | no | Codetext | AllplanAttributes - ash D_Detailverweis: <undefiniert>; Sicherheitsklasse: -; Sonnenschutztyp: Movable; g-Wert: 0,51
 | H2 Ebene +2 | WA-TL | 1205Wa 0000001309 | yes | Codetext | m² | Zimmer- und Holzbauarbeiten | Wand | Außenwand 7-Schalig | WA-TL | 0 | A | 7.5 | 1205HWa0000000029 | NEW | no | yes | 0 | 0.9 | no | 32 | no | Codetext | AllplanAttributes - ash D_Detailverweis: <undefiniert>; Sicherheitsklasse: -; Sonnenschutztyp: Movable; g-Wert: 0,51
 | H2 Ebene +2 | WA-HS | 1205Wa 0000001311 | yes | Codetext | m² | Zimmer- und Holzbauarbeiten | Wand | Außenwand 7-Schalig | WA-HS | 0 | A | 7.5 | 1205HWa0000000029 | NEW | no | yes | 0 | 0.9 | no | 32 | no | Codetext | AllplanAttributes - ash D_Detailverweis: <undefiniert>; Sicherheitsklasse: -; Sonnenschutztyp: Movable; g-Wert: 0,51
 | H2 Ebene +2 | WA-LB | 1205Wa 0000001193 | yes | Codetext | m² | Trockenbauarbeiten | Wand | Außenwand 7-Schalig | WA-LB | 0 | A | 7.5 | 1205HWa0000000998 | NEW | no | yes | 0 | 0.9 | no | 32 | no | Codetext | AllplanAttributes - ash D_Detailverweis: <undefiniert>; Sicherheitsklasse: -; Sonnenschutztyp: Movable; g-Wert: 0,51
 | H2 Ebene +2 | WA-HD | 1205Wa 0000001197 | yes | Codetext | m³ | Zimmer- und Holzbauarbeiten | Wand | Außenwand 7-Schalig | WA-HD | 0 | A | 7.5 | 1205HWa0000000998 | NEW | no | yes | 0 | 0.9 | no | 32 | no | Codetext | AllplanAttributes - ash D_Detailverweis: DT C; ash D_Plannummer: D1851; Sicherheitsklasse: -; Sonnenschutztyp: Movable; g-Wert: 0,51; ash W_laufende Nr. Statik: 2 (W 2.0/ 2.1/ 2.2)
 | H2 Ebene +2 | WA-DL | 1205Wa 0000001201 | yes | Codetext | m³ | Zimmer- und Holzbauarbeiten | Wand | Außenwand 7-Schalig | WA-DL | 0 | A | 7.5 | 1205HWa0000000998 | NEW | no | yes | 0 | 0.9 | no | 32 | no | Codetext | AllplanAttributes - ash D_Detailverweis: <undefiniert>; Sicherheitsklasse: -; Sonnenschutztyp: Movable; g-Wert: 0,51
 | H2 Ebene +2 | WA-LB | 1205Wa 0000001205 | yes | Codetext | m² | Trockenbauarbeiten | Wand | Außenwand 7-Schalig | WA-LB | 0 | A | 7.5 | 1205HWa0000000998 | NEW | no | yes | 0 | 0.9 | no | 32 | no | Codetext | AllplanAttributes - ash D_Detailverweis: <undefiniert>; Sicherheitsklasse: -; Sonnenschutztyp: Movable; g-Wert: 0,51
 | H2 Ebene +2 | WA-KL | 1205Wa 0000001209 | yes | Codetext | m² | Zimmer- und Holzbauarbeiten | Wand | Außenwand 7-Schalig | WA-KL | 0 | A | 7.5 | 1205HWa0000000998 | NEW | no | yes | 0 | 0.9 | no | 32 | no | Codetext | AllplanAttributes - ash D_Detailverweis: <undefiniert>; Sicherheitsklasse: -; Sonnenschutztyp: Movable; g-Wert: 0,51
 | H2 Ebene +2 | WA-TL | 1205Wa 0000001213 | yes | Codetext | m² | Zimmer- und Holzbauarbeiten | Wand | Außenwand 7-Schalig | WA-TL | 0 | A | 7.5 | 1205HWa0000000998 | NEW | no | yes | 0 | 0.9 | no | 32 | no | Codetext | AllplanAttributes - ash D_Detailverweis: <undefiniert>; Sicherheitsklasse: -; Sonnenschutztyp: Movable; g-Wert: 0,51
 | H2 Ebene +2 | WA-HS | 1205Wa 0000001217 | yes | Codetext | m² | Zimmer- und Holzbauarbeiten | Wand | Außenwand 7-Schalig | WA-HS | 0 | A | 7.5 | 1205HWa0000000998 | NEW | no | yes | 0 | 0.9 | no | 32 | no | Codetext | AllplanAttributes - ash D_Detailverweis: <undefiniert>; Sicherheitsklasse: -; Sonnenschutztyp: Movable; g-Wert: 0,51
 | H2 Ebene +2 | WA-LB | 1205Wa 0000001159 | yes | Codetext | m² | Trockenbauarbeiten | Wand | Außenwand 7-Schalig | WA-LB | 0 | A | 7.5 | 1205HWa0000000988 | NEW | no | yes | 0 | 0.9 | no | 35 | no | Codetext | AllplanAttributes - ash D_Detailverweis: <undefiniert>; Sicherheitsklasse: -; Sonnenschutztyp: Movable; g-Wert: 0,51
 | H2 Ebene +2 | WA-HD | 1205Wa 0000001155 | yes | Codetext | m³ | Zimmer- und Holzbauarbeiten | Wand | Außenwand 7-Schalig | WA-HD | 0 | A | 7.5 | 1205HWa0000000988 | NEW | no | yes | 0 | 0.9 | no | 35 | no | Codetext | AllplanAttributes - ash D_Detailverweis: <undefiniert>; Sicherheitsklasse: -; Sonnenschutztyp: Movable; g-Wert: 0,51; ash W_laufende Nr. Statik: 2 (W 2.0/ 2.1/ 2.2)
 | H2 Ebene +2 | WA-DL | 1205Wa 0000001135 | yes | Codetext | m³ | Zimmer- und Holzbauarbeiten | Wand | Außenwand 7-Schalig | WA-DL | 0 | A | 7.5 | 1205HWa0000000988 | NEW | no | yes | 0 | 0.9 | no | 35 | no | Codetext | AllplanAttributes - ash D_Detailverweis: <undefiniert>; Sicherheitsklasse: -; Sonnenschutztyp: Movable; g-Wert: 0,51
 | H2 Ebene +2 | WA-LB | 1205Wa 0000001139 | yes | Codetext | m² | Trockenbauarbeiten | Wand | Außenwand 7-Schalig | WA-LB | 0 | A | 7.5 | 1205HWa0000000988 | NEW | no | yes | 0 | 0.9 | no | 35 | no | Codetext | AllplanAttributes - ash D_Detailverweis: <undefiniert>; Sicherheitsklasse: -; Sonnenschutztyp: Movable; g-Wert: 0,51
 | H2 Ebene +2 | WA-KL | 1205Wa 0000001143 | yes | Codetext | m² | Zimmer- und Holzbauarbeiten | Wand | Außenwand 7-Schalig | WA-KL | 0 | A | 7.5 | 1205HWa0000000988 | NEW | no | yes | 0 | 0.9 | no | 35 | no | Codetext | AllplanAttributes - ash D_Detailverweis: <undefiniert>; Sicherheitsklasse: -; Sonnenschutztyp: Movable; g-Wert: 0,51
 | H2 Ebene +2 | WA-TL | 1205Wa 0000001147 | yes | Codetext | m² | Zimmer- und Holzbauarbeiten | Wand | Außenwand 7-Schalig | WA-TL | 0 | A | 7.5 | 1205HWa0000000988 | NEW | no | yes | 0 | 0.9 | no | 35 | no | Codetext | AllplanAttributes - ash D_Detailverweis: <undefiniert>; Sicherheitsklasse: -; Sonnenschutztyp: Movable; g-Wert: 0,51
 | H2 Ebene +2 | WA-HS | 1205Wa 0000001151 | yes | Codetext | m² | Zimmer- und Holzbauarbeiten | Wand | Außenwand 7-Schalig | WA-HS | 0 | A | 7.5 | 1205HWa0000000988 | NEW | no | yes | 0 | 0.9 | no | 35 | no | Codetext | AllplanAttributes - ash D_Detailverweis: <undefiniert>; Sicherheitsklasse: -; Sonnenschutztyp: Movable; g-Wert: 0,51
 | H2 Ebene +2 | WA-LB | 1205Wa 0000003112 | yes | Codetext | m² | Trockenbauarbeiten | Wand | Außenwand 7-Schalig | WA-LB | 0 | A | 7.5 | 1205HWa0000000985 | NEW | no | yes | 0 | 0.9 | no | 35 | no | Codetext | AllplanAttributes - ash D_Detailverweis: <undefiniert>; Sicherheitsklasse: -; Sonnenschutztyp: Movable; g-Wert: 0,51
 | H2 Ebene +2 | WA-HD | 1205Wa 0000003108 | yes | Codetext | m³ | Zimmer- und Holzbauarbeiten | Wand | Außenwand 7-Schalig | WA-HD | 0 | A | 7.5 | 1205HWa0000000985 | NEW | no | yes | 0 | 0.9 | no | 35 | no | Codetext | AllplanAttributes - ash D_Detailverweis: <undefiniert>; Sicherheitsklasse: -; Sonnenschutztyp: Movable; g-Wert: 0,51; ash W_laufende Nr. Statik: 2 (W 2.0/ 2.1/ 2.2)
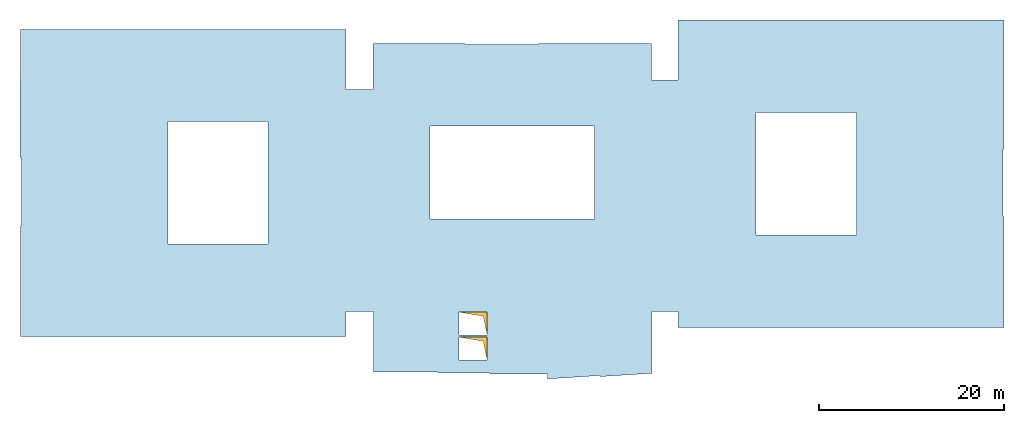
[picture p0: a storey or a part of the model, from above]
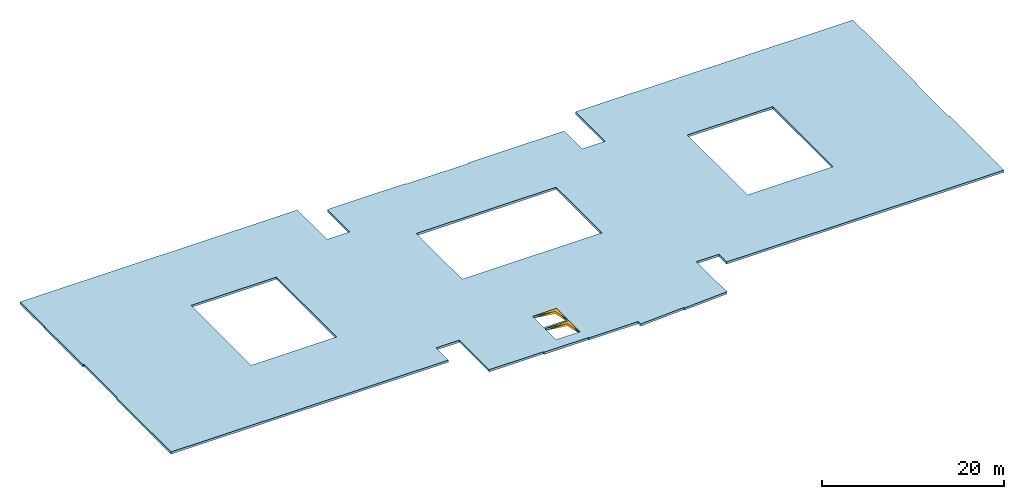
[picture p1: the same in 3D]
Properties of the parts of a building model (IFC4), part 49 of 80

# IfcWall (6826)
Name | In | Material | Allright_Bauteil_ID | 2D Interaktion | Codetext | Abrechnungsart | Gewerk | Objektname | Bezeichnung | AllplanAttributes, Material | Typ = SurfaceSpreadOfFlame | Brandschutzklasse | OKFF | P_ID | Status | LoadBearing | IsExternal | FireRating | ThermalTransmittance (W/K/m2) | Combustible | AcousticRating | Compartmentation | Reference
 | H2 Ebene +2 | WA-DL | 1205Wa 0000003104 | yes | Codetext | m³ | Zimmer- und Holzbauarbeiten | Wand | Außenwand 7-Schalig | WA-DL | 0 | A | 7.5 | 1205HWa0000000985 | NEW | no | yes | 0 | 0.9 | no | 35 | no | Codetext | AllplanAttributes - ash D_Detailverweis: <undefiniert>; Sicherheitsklasse: -; Sonnenschutztyp: Movable; g-Wert: 0,51
 | H2 Ebene +2 | WA-LB | 1205Wa 0000003100 | yes | Codetext | m² | Trockenbauarbeiten | Wand | Außenwand 7-Schalig | WA-LB | 0 | A | 7.5 | 1205HWa0000000985 | NEW | no | yes | 0 | 0.9 | no | 35 | no | Codetext | AllplanAttributes - ash D_Detailverweis: <undefiniert>; Sicherheitsklasse: -; Sonnenschutztyp: Movable; g-Wert: 0,51
 | H2 Ebene +2 | WA-KL | 1205Wa 0000003096 | yes | Codetext | m² | Zimmer- und Holzbauarbeiten | Wand | Außenwand 7-Schalig | WA-KL | 0 | A | 7.5 | 1205HWa0000000985 | NEW | no | yes | 0 | 0.9 | no | 35 | no | Codetext | AllplanAttributes - ash D_Detailverweis: <undefiniert>; Sicherheitsklasse: -; Sonnenschutztyp: Movable; g-Wert: 0,51
 | H2 Ebene +2 | WA-TL | 1205Wa 0000003092 | yes | Codetext | m² | Zimmer- und Holzbauarbeiten | Wand | Außenwand 7-Schalig | WA-TL | 0 | A | 7.5 | 1205HWa0000000985 | NEW | no | yes | 0 | 0.9 | no | 35 | no | Codetext | AllplanAttributes - ash D_Detailverweis: <undefiniert>; Sicherheitsklasse: -; Sonnenschutztyp: Movable; g-Wert: 0,51
 | H2 Ebene +2 | WA-HS | 1205Wa 0000003088 | yes | Codetext | m² | Zimmer- und Holzbauarbeiten | Wand | Außenwand 7-Schalig | WA-HS | 0 | A | 7.5 | 1205HWa0000000985 | NEW | no | yes | 0 | 0.9 | no | 35 | no | Codetext | AllplanAttributes - ash D_Detailverweis: <undefiniert>; Sicherheitsklasse: -; Sonnenschutztyp: Movable; g-Wert: 0,51
2x Gipsfaserplatte | H2 Ebene +2 | WA-LB | 1205Wa 0000003146 | yes |  | m² | Trockenbauarbeiten | Wand | 2x Gipsfaserplatte | WA-LB |  |  | 7.5 | 1205HWa0000000992 | NEW | no | yes | 0 | 0.9 |  | 35 | AllplanAttributes - ash D_Detailverweis: <undefiniert>; Sicherheitsklasse: -; Sonnenschutztyp: Movable; g-Wert: 0,51
Holzständer + Zwischendämmung | H2 Ebene +2 | WA-HD | 1205Wa 0000003144 | yes |  | m³ | Zimmer- und Holzbauarbeiten | Wand | Holzständer + Zwischendämmung | WA-HD |  |  | 7.5 | 1205HWa0000000992 | NEW | no | yes | 0 | 0.9 |  | 35 | AllplanAttributes - ash D_Detailverweis: <undefiniert>; Sicherheitsklasse: -; Sonnenschutztyp: Movable; g-Wert: 0,51; ash W_laufende Nr. Statik: 2 (W 2.0/ 2.1/ 2.2)
Staffel + Zwischendämmung | H2 Ebene +2 | WA-DL | 1205Wa 0000003142 | yes |  | m³ | Zimmer- und Holzbauarbeiten | Wand | Staffel + Zwischendämmung | WA-DL |  |  | 7.5 | 1205HWa0000000992 | NEW | no | yes | 0 | 0.9 |  | 35 | AllplanAttributes - ash D_Detailverweis: <undefiniert>; Sicherheitsklasse: -; Sonnenschutztyp: Movable; g-Wert: 0,51
 | H2 Ebene +2 | WA-LB | 1205Wa 0000003148 | yes | Codetext | m² | Trockenbauarbeiten | Wand | Außenwand 7-Schalig | WA-LB | 0 | A | 7.5 | 1205HWa0000000992 | NEW | no | yes | 0 | 0.9 | no | 35 | no | Codetext | AllplanAttributes - ash D_Detailverweis: <undefiniert>; Sicherheitsklasse: -; Sonnenschutztyp: Movable; g-Wert: 0,51
Konterlattung | H2 Ebene +2 | WA-KL | 1205Wa 0000003150 | yes |  | m² | Zimmer- und Holzbauarbeiten | Wand | Konterlattung | WA-KL |  |  | 7.5 | 1205HWa0000000992 | NEW | no | yes | 0 | 0.9 |  | 35 | AllplanAttributes - ash D_Detailverweis: <undefiniert>; Sicherheitsklasse: -; Sonnenschutztyp: Movable; g-Wert: 0,51
Traglattung | H2 Ebene +2 | WA-TL | 1205Wa 0000003152 | yes |  | m² | Zimmer- und Holzbauarbeiten | Wand | Traglattung | WA-TL |  |  | 7.5 | 1205HWa0000000992 | NEW | no | yes | 0 | 0.9 |  | 35 | AllplanAttributes - ash D_Detailverweis: <undefiniert>; Sicherheitsklasse: -; Sonnenschutztyp: Movable; g-Wert: 0,51
Holzschindel | H2 Ebene +2 | WA-HS | 1205Wa 0000003154 | yes |  | m² | Zimmer- und Holzbauarbeiten | Wand | Holzschindel | WA-HS |  |  | 7.5 | 1205HWa0000000992 | NEW | no | yes | 0 | 0.9 |  | 35 | AllplanAttributes - ash D_Detailverweis: <undefiniert>; Sicherheitsklasse: -; Sonnenschutztyp: Movable; g-Wert: 0,51
2x Gipsfaserplatte | H2 Ebene +2 | WA-LB | 1205Wa 0000001169 | yes |  | m² | Trockenbauarbeiten | Wand | 2x Gipsfaserplatte | WA-LB |  |  | 7.5 | 1205HWa0000001001 | NEW | no | yes | 0 | 0.9 |  | 35 | AllplanAttributes - ash D_Detailverweis: <undefiniert>; Sicherheitsklasse: -; Sonnenschutztyp: Movable; g-Wert: 0,51
Holzständer + Zwischendämmung | H2 Ebene +2 | WA-HD | 1205Wa 0000001087 | yes |  | m³ | Zimmer- und Holzbauarbeiten | Wand | Holzständer + Zwischendämmung | WA-HD |  |  | 7.5 | 1205HWa0000001001 | NEW | no | yes | 0 | 0.9 |  | 35 | AllplanAttributes - ash D_Detailverweis: <undefiniert>; Sicherheitsklasse: -; Sonnenschutztyp: Movable; g-Wert: 0,51; ash W_laufende Nr. Statik: 2 (W 2.0/ 2.1/ 2.2)
Staffel + Zwischendämmung | H2 Ebene +2 | WA-DL | 1205Wa 0000001089 | yes |  | m³ | Zimmer- und Holzbauarbeiten | Wand | Staffel + Zwischendämmung | WA-DL |  |  | 7.5 | 1205HWa0000001001 | NEW | no | yes | 0 | 0.9 |  | 35 | AllplanAttributes - ash D_Detailverweis: <undefiniert>; Sicherheitsklasse: -; Sonnenschutztyp: Movable; g-Wert: 0,51
 | H2 Ebene +2 | WA-LB | 1205Wa 0000001167 | yes | Codetext | m² | Trockenbauarbeiten | Wand | Außenwand 7-Schalig | WA-LB | 0 | A | 7.5 | 1205HWa0000001001 | NEW | no | yes | 0 | 0.9 | no | 35 | no | Codetext | AllplanAttributes - ash D_Detailverweis: <undefiniert>; Sicherheitsklasse: -; Sonnenschutztyp: Movable; g-Wert: 0,51
Konterlattung | H2 Ebene +2 | WA-KL | 1205Wa 0000001165 | yes |  | m² | Zimmer- und Holzbauarbeiten | Wand | Konterlattung | WA-KL |  |  | 7.5 | 1205HWa0000001001 | NEW | no | yes | 0 | 0.9 |  | 35 | AllplanAttributes - ash D_Detailverweis: <undefiniert>; Sicherheitsklasse: -; Sonnenschutztyp: Movable; g-Wert: 0,51
Traglattung | H2 Ebene +2 | WA-TL | 1205Wa 0000001163 | yes |  | m² | Zimmer- und Holzbauarbeiten | Wand | Traglattung | WA-TL |  |  | 7.5 | 1205HWa0000001001 | NEW | no | yes | 0 | 0.9 |  | 35 | AllplanAttributes - ash D_Detailverweis: <undefiniert>; Sicherheitsklasse: -; Sonnenschutztyp: Movable; g-Wert: 0,51
Holzschindel | H2 Ebene +2 | WA-HS | 1205Wa 0000001161 | yes |  | m² | Zimmer- und Holzbauarbeiten | Wand | Holzschindel | WA-HS |  |  | 7.5 | 1205HWa0000001001 | NEW | no | yes | 0 | 0.9 |  | 35 | AllplanAttributes - ash D_Detailverweis: <undefiniert>; Sicherheitsklasse: -; Sonnenschutztyp: Movable; g-Wert: 0,51
2x Gipsfaserplatte | H2 Ebene +2 | WA-LB | 1205Wa 0000001119 | yes |  | m² | Trockenbauarbeiten | Wand | 2x Gipsfaserplatte | WA-LB |  |  | 7.5 | 1205HWa0000001003 | NEW | no | yes | 0 | 0.9 |  | 35 | AllplanAttributes - ash D_Detailverweis: <undefiniert>; Sicherheitsklasse: -; Sonnenschutztyp: Movable; g-Wert: 0,51
Holzständer + Zwischendämmung | H2 Ebene +2 | WA-HD | 1205Wa 0000001121 | yes |  | m³ | Zimmer- und Holzbauarbeiten | Wand | Holzständer + Zwischendämmung | WA-HD |  |  | 7.5 | 1205HWa0000001003 | NEW | no | yes | 0 | 0.9 |  | 35 | AllplanAttributes - ash D_Detailverweis: <undefiniert>; Sicherheitsklasse: -; Sonnenschutztyp: Movable; g-Wert: 0,51; ash W_laufende Nr. Statik: 2 (W 2.0/ 2.1/ 2.2)
Staffel + Zwischendämmung | H2 Ebene +2 | WA-DL | 1205Wa 0000001123 | yes |  | m³ | Zimmer- und Holzbauarbeiten | Wand | Staffel + Zwischendämmung | WA-DL |  |  | 7.5 | 1205HWa0000001003 | NEW | no | yes | 0 | 0.9 |  | 35 | AllplanAttributes - ash D_Detailverweis: <undefiniert>; Sicherheitsklasse: -; Sonnenschutztyp: Movable; g-Wert: 0,51
 | H2 Ebene +2 | WA-LB | 1205Wa 0000001125 | yes | Codetext | m² | Trockenbauarbeiten | Wand | Außenwand 7-Schalig | WA-LB | 0 | A | 7.5 | 1205HWa0000001003 | NEW | no | yes | 0 | 0.9 | no | 35 | no | Codetext | AllplanAttributes - ash D_Detailverweis: <undefiniert>; Sicherheitsklasse: -; Sonnenschutztyp: Movable; g-Wert: 0,51
Konterlattung | H2 Ebene +2 | WA-KL | 1205Wa 0000001127 | yes |  | m² | Zimmer- und Holzbauarbeiten | Wand | Konterlattung | WA-KL |  |  | 7.5 | 1205HWa0000001003 | NEW | no | yes | 0 | 0.9 |  | 35 | AllplanAttributes - ash D_Detailverweis: <undefiniert>; Sicherheitsklasse: -; Sonnenschutztyp: Movable; g-Wert: 0,51
Traglattung | H2 Ebene +2 | WA-TL | 1205Wa 0000001129 | yes |  | m² | Zimmer- und Holzbauarbeiten | Wand | Traglattung | WA-TL |  |  | 7.5 | 1205HWa0000001003 | NEW | no | yes | 0 | 0.9 |  | 35 | AllplanAttributes - ash D_Detailverweis: <undefiniert>; Sicherheitsklasse: -; Sonnenschutztyp: Movable; g-Wert: 0,51
Holzschindel | H2 Ebene +2 | WA-HS | 1205Wa 0000001131 | yes |  | m² | Zimmer- und Holzbauarbeiten | Wand | Holzschindel | WA-HS |  |  | 7.5 | 1205HWa0000001003 | NEW | no | yes | 0 | 0.9 |  | 35 | AllplanAttributes - ash D_Detailverweis: <undefiniert>; Sicherheitsklasse: -; Sonnenschutztyp: Movable; g-Wert: 0,51
 | H2 Ebene +2 | WA-LB | 1205Wa 0000000332 | yes | Codetext | m² | Trockenbauarbeiten | Wand | Außenwand 7-Schalig | WA-LB | 0 | A | 7.5 | 1205HWa0000000194 | NEW | no | yes | 0 | 0.9 | no | 32 | no | Codetext | AllplanAttributes - ash D_Detailverweis: <undefiniert>; Sicherheitsklasse: -; Sonnenschutztyp: Movable; g-Wert: 0,51
 | H2 Ebene +2 | WA-HD | 1205Wa 0000000336 | yes | Codetext | m³ | Zimmer- und Holzbauarbeiten | Wand | Außenwand 7-Schalig | WA-HD | 0 | A | 7.5 | 1205HWa0000000194 | NEW | no | yes | 0 | 0.9 | no | 32 | no | Codetext | AllplanAttributes - ash D_Detailverweis: <undefiniert>; Sicherheitsklasse: -; Sonnenschutztyp: Movable; g-Wert: 0,51; ash W_laufende Nr. Statik: 2 (W 2.0/ 2.1/ 2.2)
 | H2 Ebene +2 | WA-DL | 1205Wa 0000000356 | yes | Codetext | m³ | Zimmer- und Holzbauarbeiten | Wand | Außenwand 7-Schalig | WA-DL | 0 | A | 7.5 | 1205HWa0000000194 | NEW | no | yes | 0 | 0.9 | no | 32 | no | Codetext | AllplanAttributes - ash D_Detailverweis: <undefiniert>; Sicherheitsklasse: -; Sonnenschutztyp: Movable; g-Wert: 0,51
 | H2 Ebene +2 | WA-LB | 1205Wa 0000000352 | yes | Codetext | m² | Trockenbauarbeiten | Wand | Außenwand 7-Schalig | WA-LB | 0 | A | 7.5 | 1205HWa0000000194 | NEW | no | yes | 0 | 0.9 | no | 32 | no | Codetext | AllplanAttributes - ash D_Detailverweis: <undefiniert>; Sicherheitsklasse: -; Sonnenschutztyp: Movable; g-Wert: 0,51
 | H2 Ebene +2 | WA-KL | 1205Wa 0000000348 | yes | Codetext | m² | Zimmer- und Holzbauarbeiten | Wand | Außenwand 7-Schalig | WA-KL | 0 | A | 7.5 | 1205HWa0000000194 | NEW | no | yes | 0 | 0.9 | no | 32 | no | Codetext | AllplanAttributes - ash D_Detailverweis: <undefiniert>; Sicherheitsklasse: -; Sonnenschutztyp: Movable; g-Wert: 0,51
 | H2 Ebene +2 | WA-TL | 1205Wa 0000000344 | yes | Codetext | m² | Zimmer- und Holzbauarbeiten | Wand | Außenwand 7-Schalig | WA-TL | 0 | A | 7.5 | 1205HWa0000000194 | NEW | no | yes | 0 | 0.9 | no | 32 | no | Codetext | AllplanAttributes - ash D_Detailverweis: <undefiniert>; Sicherheitsklasse: -; Sonnenschutztyp: Movable; g-Wert: 0,51
 | H2 Ebene +2 | WA-HS | 1205Wa 0000000340 | yes | Codetext | m² | Zimmer- und Holzbauarbeiten | Wand | Außenwand 7-Schalig | WA-HS | 0 | A | 7.5 | 1205HWa0000000194 | NEW | no | yes | 0 | 0.9 | no | 32 | no | Codetext | AllplanAttributes - ash D_Detailverweis: <undefiniert>; Sicherheitsklasse: -; Sonnenschutztyp: Movable; g-Wert: 0,51
 | H2 Ebene +2 | WA-LB | 1205Wa 0000000388 | yes | Codetext | m² | Trockenbauarbeiten | Wand | Außenwand 7-Schalig | WA-LB | 0 | A | 7.5 | 1205HWa0000000188 | NEW | no | yes | 0 | 0.9 | no | 32 | no | Codetext | AllplanAttributes - ash D_Detailverweis: <undefiniert>; Sicherheitsklasse: -; Sonnenschutztyp: Movable; g-Wert: 0,51
 | H2 Ebene +2 | WA-HD | 1205Wa 0000000384 | yes | Codetext | m³ | Zimmer- und Holzbauarbeiten | Wand | Außenwand 7-Schalig | WA-HD | 0 | A | 7.5 | 1205HWa0000000188 | NEW | no | yes | 0 | 0.9 | no | 32 | no | Codetext | AllplanAttributes - ash D_Detailverweis: <undefiniert>; Sicherheitsklasse: -; Sonnenschutztyp: Movable; g-Wert: 0,51; ash W_laufende Nr. Statik: 2 (W 2.0/ 2.1/ 2.2)
 | H2 Ebene +2 | WA-DL | 1205Wa 0000000364 | yes | Codetext | m³ | Zimmer- und Holzbauarbeiten | Wand | Außenwand 7-Schalig | WA-DL | 0 | A | 7.5 | 1205HWa0000000188 | NEW | no | yes | 0 | 0.9 | no | 32 | no | Codetext | AllplanAttributes - ash D_Detailverweis: <undefiniert>; Sicherheitsklasse: -; Sonnenschutztyp: Movable; g-Wert: 0,51
 | H2 Ebene +2 | WA-LB | 1205Wa 0000000368 | yes | Codetext | m² | Trockenbauarbeiten | Wand | Außenwand 7-Schalig | WA-LB | 0 | A | 7.5 | 1205HWa0000000188 | NEW | no | yes | 0 | 0.9 | no | 32 | no | Codetext | AllplanAttributes - ash D_Detailverweis: <undefiniert>; Sicherheitsklasse: -; Sonnenschutztyp: Movable; g-Wert: 0,51
 | H2 Ebene +2 | WA-KL | 1205Wa 0000000372 | yes | Codetext | m² | Zimmer- und Holzbauarbeiten | Wand | Außenwand 7-Schalig | WA-KL | 0 | A | 7.5 | 1205HWa0000000188 | NEW | no | yes | 0 | 0.9 | no | 32 | no | Codetext | AllplanAttributes - ash D_Detailverweis: <undefiniert>; Sicherheitsklasse: -; Sonnenschutztyp: Movable; g-Wert: 0,51
 | H2 Ebene +2 | WA-TL | 1205Wa 0000000376 | yes | Codetext | m² | Zimmer- und Holzbauarbeiten | Wand | Außenwand 7-Schalig | WA-TL | 0 | A | 7.5 | 1205HWa0000000188 | NEW | no | yes | 0 | 0.9 | no | 32 | no | Codetext | AllplanAttributes - ash D_Detailverweis: <undefiniert>; Sicherheitsklasse: -; Sonnenschutztyp: Movable; g-Wert: 0,51
 | H2 Ebene +2 | WA-HS | 1205Wa 0000000380 | yes | Codetext | m² | Zimmer- und Holzbauarbeiten | Wand | Außenwand 7-Schalig | WA-HS | 0 | A | 7.5 | 1205HWa0000000188 | NEW | no | yes | 0 | 0.9 | no | 32 | no | Codetext | AllplanAttributes - ash D_Detailverweis: <undefiniert>; Sicherheitsklasse: -; Sonnenschutztyp: Movable; g-Wert: 0,51
2x Gipsfaserplatte | H2 Ebene +2 | WA-LB | 1205Wa 0000000398 | yes |  | m² | Trockenbauarbeiten | Wand | 2x Gipsfaserplatte | WA-LB |  |  | 7.5 | 1205HWa0000000201 | NEW | no | yes | 0 | 0.9 |  | 32 | AllplanAttributes - ash D_Detailverweis: <undefiniert>; Sicherheitsklasse: -; Sonnenschutztyp: Movable; g-Wert: 0,51
Holzständer + Zwischendämmung | H2 Ebene +2 | WA-HD | 1205Wa 0000000326 | yes |  | m³ | Zimmer- und Holzbauarbeiten | Wand | Holzständer + Zwischendämmung | WA-HD |  |  | 7.5 | 1205HWa0000000201 | NEW | no | yes | 0 | 0.9 |  | 32 | AllplanAttributes - ash D_Detailverweis: <undefiniert>; Sicherheitsklasse: -; Sonnenschutztyp: Movable; g-Wert: 0,51; ash W_laufende Nr. Statik: 2 (W 2.0/ 2.1/ 2.2)
Staffel + Zwischendämmung | H2 Ebene +2 | WA-DL | 1205Wa 0000000328 | yes |  | m³ | Zimmer- und Holzbauarbeiten | Wand | Staffel + Zwischendämmung | WA-DL |  |  | 7.5 | 1205HWa0000000201 | NEW | no | yes | 0 | 0.9 |  | 32 | AllplanAttributes - ash D_Detailverweis: <undefiniert>; Sicherheitsklasse: -; Sonnenschutztyp: Movable; g-Wert: 0,51
 | H2 Ebene +2 | WA-LB | 1205Wa 0000000396 | yes | Codetext | m² | Trockenbauarbeiten | Wand | Außenwand 7-Schalig | WA-LB | 0 | A | 7.5 | 1205HWa0000000201 | NEW | no | yes | 0 | 0.9 | no | 32 | no | Codetext | AllplanAttributes - ash D_Detailverweis: <undefiniert>; Sicherheitsklasse: -; Sonnenschutztyp: Movable; g-Wert: 0,51
Konterlattung | H2 Ebene +2 | WA-KL | 1205Wa 0000000394 | yes |  | m² | Zimmer- und Holzbauarbeiten | Wand | Konterlattung | WA-KL |  |  | 7.5 | 1205HWa0000000201 | NEW | no | yes | 0 | 0.9 |  | 32 | AllplanAttributes - ash D_Detailverweis: <undefiniert>; Sicherheitsklasse: -; Sonnenschutztyp: Movable; g-Wert: 0,51
Traglattung | H2 Ebene +2 | WA-TL | 1205Wa 0000000392 | yes |  | m² | Zimmer- und Holzbauarbeiten | Wand | Traglattung | WA-TL |  |  | 7.5 | 1205HWa0000000201 | NEW | no | yes | 0 | 0.9 |  | 32 | AllplanAttributes - ash D_Detailverweis: <undefiniert>; Sicherheitsklasse: -; Sonnenschutztyp: Movable; g-Wert: 0,51
Holzschindel | H2 Ebene +2 | WA-HS | 1205Wa 0000000390 | yes |  | m² | Zimmer- und Holzbauarbeiten | Wand | Holzschindel | WA-HS |  |  | 7.5 | 1205HWa0000000201 | NEW | no | yes | 0 | 0.9 |  | 32 | AllplanAttributes - ash D_Detailverweis: <undefiniert>; Sicherheitsklasse: -; Sonnenschutztyp: Movable; g-Wert: 0,51
2x Gipsfaserplatte | H2 Ebene +2 | WA-LB | 1205Wa 0000000400 | yes |  | m² | Trockenbauarbeiten | Wand | 2x Gipsfaserplatte | WA-LB |  |  | 7.5 | 1205HWa0000000192 | NEW | no | yes | 0 | 0.9 |  | 32 | AllplanAttributes - ash D_Detailverweis: <undefiniert>; Sicherheitsklasse: -; Sonnenschutztyp: Movable; g-Wert: 0,51
Holzständer + Zwischendämmung | H2 Ebene +2 | WA-HD | 1205Wa 0000000360 | yes |  | m³ | Zimmer- und Holzbauarbeiten | Wand | Holzständer + Zwischendämmung | WA-HD |  |  | 7.5 | 1205HWa0000000192 | NEW | no | yes | 0 | 0.9 |  | 32 | AllplanAttributes - ash D_Detailverweis: <undefiniert>; Sicherheitsklasse: -; Sonnenschutztyp: Movable; g-Wert: 0,51; ash W_laufende Nr. Statik: 2 (W 2.0/ 2.1/ 2.2)
Staffel + Zwischendämmung | H2 Ebene +2 | WA-DL | 1205Wa 0000000358 | yes |  | m³ | Zimmer- und Holzbauarbeiten | Wand | Staffel + Zwischendämmung | WA-DL |  |  | 7.5 | 1205HWa0000000192 | NEW | no | yes | 0 | 0.9 |  | 32 | AllplanAttributes - ash D_Detailverweis: <undefiniert>; Sicherheitsklasse: -; Sonnenschutztyp: Movable; g-Wert: 0,51
 | H2 Ebene +2 | WA-LB | 1205Wa 0000000430 | yes | Codetext | m² | Trockenbauarbeiten | Wand | Außenwand 7-Schalig | WA-LB | 0 | A | 7.5 | 1205HWa0000000192 | NEW | no | yes | 0 | 0.9 | no | 32 | no | Codetext | AllplanAttributes - ash D_Detailverweis: <undefiniert>; Sicherheitsklasse: -; Sonnenschutztyp: Movable; g-Wert: 0,51
Konterlattung | H2 Ebene +2 | WA-KL | 1205Wa 0000000432 | yes |  | m² | Zimmer- und Holzbauarbeiten | Wand | Konterlattung | WA-KL |  |  | 7.5 | 1205HWa0000000192 | NEW | no | yes | 0 | 0.9 |  | 32 | AllplanAttributes - ash D_Detailverweis: <undefiniert>; Sicherheitsklasse: -; Sonnenschutztyp: Movable; g-Wert: 0,51
Traglattung | H2 Ebene +2 | WA-TL | 1205Wa 0000000434 | yes |  | m² | Zimmer- und Holzbauarbeiten | Wand | Traglattung | WA-TL |  |  | 7.5 | 1205HWa0000000192 | NEW | no | yes | 0 | 0.9 |  | 32 | AllplanAttributes - ash D_Detailverweis: <undefiniert>; Sicherheitsklasse: -; Sonnenschutztyp: Movable; g-Wert: 0,51
Holzschindel | H2 Ebene +2 | WA-HS | 1205Wa 0000000436 | yes |  | m² | Zimmer- und Holzbauarbeiten | Wand | Holzschindel | WA-HS |  |  | 7.5 | 1205HWa0000000192 | NEW | no | yes | 0 | 0.9 |  | 32 | AllplanAttributes - ash D_Detailverweis: <undefiniert>; Sicherheitsklasse: -; Sonnenschutztyp: Movable; g-Wert: 0,51
 | H2 Ebene +2 | WA-LB | 1205Wa 0000002699 | yes | Codetext | m² | Trockenbauarbeiten | Wand | Außenwand 7-Schalig | WA-LB | 0 | A | 7.5 | 1205HWa0000002199 | NEW | no | yes | 0 | 0.9 | no | 32 | no | Codetext | AllplanAttributes - ash D_Detailverweis: <undefiniert>; Sicherheitsklasse: -; Sonnenschutztyp: Movable; g-Wert: 0,51
 | H2 Ebene +2 | WA-HD | 1205Wa 0000002706 | yes | Codetext | m³ | Zimmer- und Holzbauarbeiten | Wand | Außenwand 7-Schalig | WA-HD | 0 | A | 7.5 | 1205HWa0000002199 | NEW | no | yes | 0 | 0.9 | no | 32 | no | Codetext | AllplanAttributes - ash D_Detailverweis: DT C; ash D_Plannummer: D1851; Sicherheitsklasse: -; Sonnenschutztyp: Movable; g-Wert: 0,51; ash W_laufende Nr. Statik: 2 (W 2.0/ 2.1/ 2.2)
 | H2 Ebene +2 | WA-DL | 1205Wa 0000002713 | yes | Codetext | m³ | Zimmer- und Holzbauarbeiten | Wand | Außenwand 7-Schalig | WA-DL | 0 | A | 7.5 | 1205HWa0000002199 | NEW | no | yes | 0 | 0.9 | no | 32 | no | Codetext | AllplanAttributes - ash D_Detailverweis: <undefiniert>; Sicherheitsklasse: -; Sonnenschutztyp: Movable; g-Wert: 0,51
 | H2 Ebene +2 | WA-LB | 1205Wa 0000002720 | yes | Codetext | m² | Trockenbauarbeiten | Wand | Außenwand 7-Schalig | WA-LB | 0 | A | 7.5 | 1205HWa0000002199 | NEW | no | yes | 0 | 0.9 | no | 32 | no | Codetext | AllplanAttributes - ash D_Detailverweis: <undefiniert>; Sicherheitsklasse: -; Sonnenschutztyp: Movable; g-Wert: 0,51
 | H2 Ebene +2 | WA-KL | 1205Wa 0000002727 | yes | Codetext | m² | Zimmer- und Holzbauarbeiten | Wand | Außenwand 7-Schalig | WA-KL | 0 | A | 7.5 | 1205HWa0000002199 | NEW | no | yes | 0 | 0.9 | no | 32 | no | Codetext | AllplanAttributes - ash D_Detailverweis: <undefiniert>; Sicherheitsklasse: -; Sonnenschutztyp: Movable; g-Wert: 0,51
 | H2 Ebene +2 | WA-TL | 1205Wa 0000002734 | yes | Codetext | m² | Zimmer- und Holzbauarbeiten | Wand | Außenwand 7-Schalig | WA-TL | 0 | A | 7.5 | 1205HWa0000002199 | NEW | no | yes | 0 | 0.9 | no | 32 | no | Codetext | AllplanAttributes - ash D_Detailverweis: <undefiniert>; Sicherheitsklasse: -; Sonnenschutztyp: Movable; g-Wert: 0,51
 | H2 Ebene +2 | WA-HS | 1205Wa 0000002741 | yes | Codetext | m² | Zimmer- und Holzbauarbeiten | Wand | Außenwand 7-Schalig | WA-HS | 0 | A | 7.5 | 1205HWa0000002199 | NEW | no | yes | 0 | 0.9 | no | 32 | no | Codetext | AllplanAttributes - ash D_Detailverweis: <undefiniert>; Sicherheitsklasse: -; Sonnenschutztyp: Movable; g-Wert: 0,51
 | H2 Ebene +2 | WA-LB | 1205Wa 0000002676 | yes | Codetext | m² | Trockenbauarbeiten | Wand | Außenwand 7-Schalig | WA-LB | 0 | A | 7.5 | 1205HWa0000002426 | NEW | no | yes | 0 | 0.9 | no | 32 | no | Codetext | AllplanAttributes - ash D_Detailverweis: <undefiniert>; Sicherheitsklasse: -; Sonnenschutztyp: Movable; g-Wert: 0,51
 | H2 Ebene +2 | WA-HD | 1205Wa 0000002672 | yes | Codetext | m³ | Zimmer- und Holzbauarbeiten | Wand | Außenwand 7-Schalig | WA-HD | 0 | A | 7.5 | 1205HWa0000002426 | NEW | no | yes | 0 | 0.9 | no | 32 | no | Codetext | AllplanAttributes - ash D_Detailverweis: <undefiniert>; Sicherheitsklasse: -; Sonnenschutztyp: Movable; g-Wert: 0,51; ash W_laufende Nr. Statik: 5 (W 4.0)
 | H2 Ebene +2 | WA-DL | 1205Wa 0000002668 | yes | Codetext | m³ | Zimmer- und Holzbauarbeiten | Wand | Außenwand 7-Schalig | WA-DL | 0 | A | 7.5 | 1205HWa0000002426 | NEW | no | yes | 0 | 0.9 | no | 32 | no | Codetext | AllplanAttributes - ash D_Detailverweis: <undefiniert>; Sicherheitsklasse: -; Sonnenschutztyp: Movable; g-Wert: 0,51
 | H2 Ebene +2 | WA-LB | 1205Wa 0000002664 | yes | Codetext | m² | Trockenbauarbeiten | Wand | Außenwand 7-Schalig | WA-LB | 0 | A | 7.5 | 1205HWa0000002426 | NEW | no | yes | 0 | 0.9 | no | 32 | no | Codetext | AllplanAttributes - ash D_Detailverweis: <undefiniert>; Sicherheitsklasse: -; Sonnenschutztyp: Movable; g-Wert: 0,51
 | H2 Ebene +2 | WA-KL | 1205Wa 0000002660 | yes | Codetext | m² | Zimmer- und Holzbauarbeiten | Wand | Außenwand 7-Schalig | WA-KL | 0 | A | 7.5 | 1205HWa0000002426 | NEW | no | yes | 0 | 0.9 | no | 32 | no | Codetext | AllplanAttributes - ash D_Detailverweis: <undefiniert>; Sicherheitsklasse: -; Sonnenschutztyp: Movable; g-Wert: 0,51
 | H2 Ebene +2 | WA-TL | 1205Wa 0000002656 | yes | Codetext | m² | Zimmer- und Holzbauarbeiten | Wand | Außenwand 7-Schalig | WA-TL | 0 | A | 7.5 | 1205HWa0000002426 | NEW | no | yes | 0 | 0.9 | no | 32 | no | Codetext | AllplanAttributes - ash D_Detailverweis: <undefiniert>; Sicherheitsklasse: -; Sonnenschutztyp: Movable; g-Wert: 0,51
 | H2 Ebene +2 | WA-HS | 1205Wa 0000002652 | yes | Codetext | m² | Zimmer- und Holzbauarbeiten | Wand | Außenwand 7-Schalig | WA-HS | 0 | A | 7.5 | 1205HWa0000002426 | NEW | no | yes | 0 | 0.9 | no | 32 | no | Codetext | AllplanAttributes - ash D_Detailverweis: <undefiniert>; Sicherheitsklasse: -; Sonnenschutztyp: Movable; g-Wert: 0,51
 | H2 Ebene +2 | WA-LB | 1205Wa 0000002556 | yes | Codetext | m² | Trockenbauarbeiten | Wand | Außenwand 7-Schalig | WA-LB | 0 | A | 7.5 | 1205HWa0000002503 | NEW | no | yes | 0 | 0.9 | no | 32 | no | Codetext | AllplanAttributes - ash D_Detailverweis: <undefiniert>; Sicherheitsklasse: -; Sonnenschutztyp: Movable; g-Wert: 0,51
 | H2 Ebene +2 | WA-HD | 1205Wa 0000002554 | yes | Codetext | m³ | Zimmer- und Holzbauarbeiten | Wand | Außenwand 7-Schalig | WA-HD | 0 | A | 7.5 | 1205HWa0000002503 | NEW | no | yes | 0 | 0.9 | no | 32 | no | Codetext | AllplanAttributes - ash D_Detailverweis: <undefiniert>; Sicherheitsklasse: -; Sonnenschutztyp: Movable; g-Wert: 0,51; ash W_laufende Nr. Statik: 5 (W 4.0)
 | H2 Ebene +2 | WA-DL | 1205Wa 0000002552 | yes | Codetext | m³ | Zimmer- und Holzbauarbeiten | Wand | Außenwand 7-Schalig | WA-DL | 0 | A | 7.5 | 1205HWa0000002503 | NEW | no | yes | 0 | 0.9 | no | 32 | no | Codetext | AllplanAttributes - ash D_Detailverweis: <undefiniert>; Sicherheitsklasse: -; Sonnenschutztyp: Movable; g-Wert: 0,51
 | H2 Ebene +2 | WA-LB | 1205Wa 0000002550 | yes | Codetext | m² | Trockenbauarbeiten | Wand | Außenwand 7-Schalig | WA-LB | 0 | A | 7.5 | 1205HWa0000002503 | NEW | no | yes | 0 | 0.9 | no | 32 | no | Codetext | AllplanAttributes - ash D_Detailverweis: <undefiniert>; Sicherheitsklasse: -; Sonnenschutztyp: Movable; g-Wert: 0,51
 | H2 Ebene +2 | WA-KL | 1205Wa 0000002548 | yes | Codetext | m² | Zimmer- und Holzbauarbeiten | Wand | Außenwand 7-Schalig | WA-KL | 0 | A | 7.5 | 1205HWa0000002503 | NEW | no | yes | 0 | 0.9 | no | 32 | no | Codetext | AllplanAttributes - ash D_Detailverweis: <undefiniert>; Sicherheitsklasse: -; Sonnenschutztyp: Movable; g-Wert: 0,51
 | H2 Ebene +2 | WA-TL | 1205Wa 0000002546 | yes | Codetext | m² | Zimmer- und Holzbauarbeiten | Wand | Außenwand 7-Schalig | WA-TL | 0 | A | 7.5 | 1205HWa0000002503 | NEW | no | yes | 0 | 0.9 | no | 32 | no | Codetext | AllplanAttributes - ash D_Detailverweis: <undefiniert>; Sicherheitsklasse: -; Sonnenschutztyp: Movable; g-Wert: 0,51
 | H2 Ebene +2 | WA-HS | 1205Wa 0000002544 | yes | Codetext | m² | Zimmer- und Holzbauarbeiten | Wand | Außenwand 7-Schalig | WA-HS | 0 | A | 7.5 | 1205HWa0000002503 | NEW | no | yes | 0 | 0.9 | no | 32 | no | Codetext | AllplanAttributes - ash D_Detailverweis: <undefiniert>; Sicherheitsklasse: -; Sonnenschutztyp: Movable; g-Wert: 0,51
 | H2 Ebene +2 | WA-LB | 1205Wa 0000000910 | yes | Codetext | m² | Trockenbauarbeiten | Wand | Außenwand 7-Schalig | WA-LB | 0 | A | 7.5 | 1205HWa0000000811 | NEW | no | yes | 0 | 0.9 | no | 32 | no | Codetext | AllplanAttributes - ash D_Detailverweis: <undefiniert>; Sicherheitsklasse: -; Sonnenschutztyp: Movable; g-Wert: 0,51
 | H2 Ebene +2 | WA-HD | 1205Wa 0000000914 | yes | Codetext | m³ | Zimmer- und Holzbauarbeiten | Wand | Außenwand 7-Schalig | WA-HD | 0 | A | 7.5 | 1205HWa0000000811 | NEW | no | yes | 0 | 0.9 | no | 32 | no | Codetext | AllplanAttributes - ash D_Detailverweis: <undefiniert>; Sicherheitsklasse: -; Sonnenschutztyp: Movable; g-Wert: 0,51; ash W_laufende Nr. Statik: 2 (W 2.0/ 2.1/ 2.2)
 | H2 Ebene +2 | WA-DL | 1205Wa 0000000934 | yes | Codetext | m³ | Zimmer- und Holzbauarbeiten | Wand | Außenwand 7-Schalig | WA-DL | 0 | A | 7.5 | 1205HWa0000000811 | NEW | no | yes | 0 | 0.9 | no | 32 | no | Codetext | AllplanAttributes - ash D_Detailverweis: <undefiniert>; Sicherheitsklasse: -; Sonnenschutztyp: Movable; g-Wert: 0,51
 | H2 Ebene +2 | WA-LB | 1205Wa 0000000930 | yes | Codetext | m² | Trockenbauarbeiten | Wand | Außenwand 7-Schalig | WA-LB | 0 | A | 7.5 | 1205HWa0000000811 | NEW | no | yes | 0 | 0.9 | no | 32 | no | Codetext | AllplanAttributes - ash D_Detailverweis: <undefiniert>; Sicherheitsklasse: -; Sonnenschutztyp: Movable; g-Wert: 0,51
 | H2 Ebene +2 | WA-KL | 1205Wa 0000000926 | yes | Codetext | m² | Zimmer- und Holzbauarbeiten | Wand | Außenwand 7-Schalig | WA-KL | 0 | A | 7.5 | 1205HWa0000000811 | NEW | no | yes | 0 | 0.9 | no | 32 | no | Codetext | AllplanAttributes - ash D_Detailverweis: <undefiniert>; Sicherheitsklasse: -; Sonnenschutztyp: Movable; g-Wert: 0,51
 | H2 Ebene +2 | WA-TL | 1205Wa 0000000922 | yes | Codetext | m² | Zimmer- und Holzbauarbeiten | Wand | Außenwand 7-Schalig | WA-TL | 0 | A | 7.5 | 1205HWa0000000811 | NEW | no | yes | 0 | 0.9 | no | 32 | no | Codetext | AllplanAttributes - ash D_Detailverweis: <undefiniert>; Sicherheitsklasse: -; Sonnenschutztyp: Movable; g-Wert: 0,51
 | H2 Ebene +2 | WA-HS | 1205Wa 0000000918 | yes | Codetext | m² | Zimmer- und Holzbauarbeiten | Wand | Außenwand 7-Schalig | WA-HS | 0 | A | 7.5 | 1205HWa0000000811 | NEW | no | yes | 0 | 0.9 | no | 32 | no | Codetext | AllplanAttributes - ash D_Detailverweis: <undefiniert>; Sicherheitsklasse: -; Sonnenschutztyp: Movable; g-Wert: 0,51
 | H2 Ebene +2 | WA-LB | 1205Wa 0000002807 | yes | Codetext | m² | Trockenbauarbeiten | Wand | Außenwand 7-Schalig | WA-LB | 0 | A | 7.5 | 1205HWa0000000808 | NEW | no | yes | 0 | 0.9 | no | 32 | no | Codetext | AllplanAttributes - ash D_Detailverweis: <undefiniert>; Sicherheitsklasse: -; Sonnenschutztyp: Movable; g-Wert: 0,51
 | H2 Ebene +2 | WA-HD | 1205Wa 0000002803 | yes | Codetext | m³ | Zimmer- und Holzbauarbeiten | Wand | Außenwand 7-Schalig | WA-HD | 0 | A | 7.5 | 1205HWa0000000808 | NEW | no | yes | 0 | 0.9 | no | 32 | no | Codetext | AllplanAttributes - ash D_Detailverweis: <undefiniert>; Sicherheitsklasse: -; Sonnenschutztyp: Movable; g-Wert: 0,51; ash W_laufende Nr. Statik: 2 (W 2.0/ 2.1/ 2.2)
 | H2 Ebene +2 | WA-DL | 1205Wa 0000002799 | yes | Codetext | m³ | Zimmer- und Holzbauarbeiten | Wand | Außenwand 7-Schalig | WA-DL | 0 | A | 7.5 | 1205HWa0000000808 | NEW | no | yes | 0 | 0.9 | no | 32 | no | Codetext | AllplanAttributes - ash D_Detailverweis: <undefiniert>; Sicherheitsklasse: -; Sonnenschutztyp: Movable; g-Wert: 0,51
 | H2 Ebene +2 | WA-LB | 1205Wa 0000002795 | yes | Codetext | m² | Trockenbauarbeiten | Wand | Außenwand 7-Schalig | WA-LB | 0 | A | 7.5 | 1205HWa0000000808 | NEW | no | yes | 0 | 0.9 | no | 32 | no | Codetext | AllplanAttributes - ash D_Detailverweis: <undefiniert>; Sicherheitsklasse: -; Sonnenschutztyp: Movable; g-Wert: 0,51
 | H2 Ebene +2 | WA-KL | 1205Wa 0000002791 | yes | Codetext | m² | Zimmer- und Holzbauarbeiten | Wand | Außenwand 7-Schalig | WA-KL | 0 | A | 7.5 | 1205HWa0000000808 | NEW | no | yes | 0 | 0.9 | no | 32 | no | Codetext | AllplanAttributes - ash D_Detailverweis: <undefiniert>; Sicherheitsklasse: -; Sonnenschutztyp: Movable; g-Wert: 0,51
 | H2 Ebene +2 | WA-TL | 1205Wa 0000002787 | yes | Codetext | m² | Zimmer- und Holzbauarbeiten | Wand | Außenwand 7-Schalig | WA-TL | 0 | A | 7.5 | 1205HWa0000000808 | NEW | no | yes | 0 | 0.9 | no | 32 | no | Codetext | AllplanAttributes - ash D_Detailverweis: <undefiniert>; Sicherheitsklasse: -; Sonnenschutztyp: Movable; g-Wert: 0,51
 | H2 Ebene +2 | WA-HS | 1205Wa 0000002783 | yes | Codetext | m² | Zimmer- und Holzbauarbeiten | Wand | Außenwand 7-Schalig | WA-HS | 0 | A | 7.5 | 1205HWa0000000808 | NEW | no | yes | 0 | 0.9 | no | 32 | no | Codetext | AllplanAttributes - ash D_Detailverweis: <undefiniert>; Sicherheitsklasse: -; Sonnenschutztyp: Movable; g-Wert: 0,51
2x Gipsfaserplatte | H2 Ebene +2 | WA-LB | 1205Wa 0000002831 | yes |  | m² | Trockenbauarbeiten | Wand | 2x Gipsfaserplatte | WA-LB |  |  | 7.5 | 1205HWa0000000815 | NEW | no | yes | 0 | 0.9 |  | 32 | AllplanAttributes - ash D_Detailverweis: <undefiniert>; Sicherheitsklasse: -; Sonnenschutztyp: Movable; g-Wert: 0,51
Holzständer + Zwischendämmung | H2 Ebene +2 | WA-HD | 1205Wa 0000002833 | yes |  | m³ | Zimmer- und Holzbauarbeiten | Wand | Holzständer + Zwischendämmung | WA-HD |  |  | 7.5 | 1205HWa0000000815 | NEW | no | yes | 0 | 0.9 |  | 32 | AllplanAttributes - ash D_Detailverweis: <undefiniert>; Sicherheitsklasse: -; Sonnenschutztyp: Movable; g-Wert: 0,51; ash W_laufende Nr. Statik: 2 (W 2.0/ 2.1/ 2.2)
Staffel + Zwischendämmung | H2 Ebene +2 | WA-DL | 1205Wa 0000002835 | yes |  | m³ | Zimmer- und Holzbauarbeiten | Wand | Staffel + Zwischendämmung | WA-DL |  |  | 7.5 | 1205HWa0000000815 | NEW | no | yes | 0 | 0.9 |  | 32 | AllplanAttributes - ash D_Detailverweis: <undefiniert>; Sicherheitsklasse: -; Sonnenschutztyp: Movable; g-Wert: 0,51
 | H2 Ebene +2 | WA-LB | 1205Wa 0000002829 | yes | Codetext | m² | Trockenbauarbeiten | Wand | Außenwand 7-Schalig | WA-LB | 0 | A | 7.5 | 1205HWa0000000815 | NEW | no | yes | 0 | 0.9 | no | 32 | no | Codetext | AllplanAttributes - ash D_Detailverweis: <undefiniert>; Sicherheitsklasse: -; Sonnenschutztyp: Movable; g-Wert: 0,51
Konterlattung | H2 Ebene +2 | WA-KL | 1205Wa 0000002827 | yes |  | m² | Zimmer- und Holzbauarbeiten | Wand | Konterlattung | WA-KL |  |  | 7.5 | 1205HWa0000000815 | NEW | no | yes | 0 | 0.9 |  | 32 | AllplanAttributes - ash D_Detailverweis: <undefiniert>; Sicherheitsklasse: -; Sonnenschutztyp: Movable; g-Wert: 0,51
Traglattung | H2 Ebene +2 | WA-TL | 1205Wa 0000002825 | yes |  | m² | Zimmer- und Holzbauarbeiten | Wand | Traglattung | WA-TL |  |  | 7.5 | 1205HWa0000000815 | NEW | no | yes | 0 | 0.9 |  | 32 | AllplanAttributes - ash D_Detailverweis: <undefiniert>; Sicherheitsklasse: -; Sonnenschutztyp: Movable; g-Wert: 0,51
Holzschindel | H2 Ebene +2 | WA-HS | 1205Wa 0000002823 | yes |  | m² | Zimmer- und Holzbauarbeiten | Wand | Holzschindel | WA-HS |  |  | 7.5 | 1205HWa0000000815 | NEW | no | yes | 0 | 0.9 |  | 32 | AllplanAttributes - ash D_Detailverweis: <undefiniert>; Sicherheitsklasse: -; Sonnenschutztyp: Movable; g-Wert: 0,51
2x Gipsfaserplatte | H2 Ebene +2 | WA-LB | 1205Wa 0000002877 | yes |  | m² | Trockenbauarbeiten | Wand | 2x Gipsfaserplatte | WA-LB |  |  | 7.5 | 1205HWa0000002751 | NEW | no | yes | 0 | 0.9 |  | 32 | AllplanAttributes - ash D_Detailverweis: <undefiniert>; Sicherheitsklasse: -; Sonnenschutztyp: Movable; g-Wert: 0,51
Holzständer + Zwischendämmung | H2 Ebene +2 | WA-HD | 1205Wa 0000002875 | yes |  | m³ | Zimmer- und Holzbauarbeiten | Wand | Holzständer + Zwischendämmung | WA-HD |  |  | 7.5 | 1205HWa0000002751 | NEW | no | yes | 0 | 0.9 |  | 32 | AllplanAttributes - ash D_Detailverweis: <undefiniert>; Sicherheitsklasse: -; Sonnenschutztyp: Movable; g-Wert: 0,51; ash W_laufende Nr. Statik: 5 (W 4.0)
Staffel + Zwischendämmung | H2 Ebene +2 | WA-DL | 1205Wa 0000002873 | yes |  | m³ | Zimmer- und Holzbauarbeiten | Wand | Staffel + Zwischendämmung | WA-DL |  |  | 7.5 | 1205HWa0000002751 | NEW | no | yes | 0 | 0.9 |  | 32 | AllplanAttributes - ash D_Detailverweis: <undefiniert>; Sicherheitsklasse: -; Sonnenschutztyp: Movable; g-Wert: 0,51
 | H2 Ebene +2 | WA-LB | 1205Wa 0000002871 | yes | Codetext | m² | Trockenbauarbeiten | Wand | Außenwand 7-Schalig | WA-LB | 0 | A | 7.5 | 1205HWa0000002751 | NEW | no | yes | 0 | 0.9 | no | 32 | no | Codetext | AllplanAttributes - ash D_Detailverweis: <undefiniert>; Sicherheitsklasse: -; Sonnenschutztyp: Movable; g-Wert: 0,51
Konterlattung | H2 Ebene +2 | WA-KL | 1205Wa 0000002869 | yes |  | m² | Zimmer- und Holzbauarbeiten | Wand | Konterlattung | WA-KL |  |  | 7.5 | 1205HWa0000002751 | NEW | no | yes | 0 | 0.9 |  | 32 | AllplanAttributes - ash D_Detailverweis: <undefiniert>; Sicherheitsklasse: -; Sonnenschutztyp: Movable; g-Wert: 0,51
Traglattung | H2 Ebene +2 | WA-TL | 1205Wa 0000002867 | yes |  | m² | Zimmer- und Holzbauarbeiten | Wand | Traglattung | WA-TL |  |  | 7.5 | 1205HWa0000002751 | NEW | no | yes | 0 | 0.9 |  | 32 | AllplanAttributes - ash D_Detailverweis: <undefiniert>; Sicherheitsklasse: -; Sonnenschutztyp: Movable; g-Wert: 0,51
Holzschindel | H2 Ebene +2 | WA-HS | 1205Wa 0000002865 | yes |  | m² | Zimmer- und Holzbauarbeiten | Wand | Holzschindel | WA-HS |  |  | 7.5 | 1205HWa0000002751 | NEW | no | yes | 0 | 0.9 |  | 32 | AllplanAttributes - ash D_Detailverweis: <undefiniert>; Sicherheitsklasse: -; Sonnenschutztyp: Movable; g-Wert: 0,51
2x Gipsfaserplatte | H2 Ebene +2 | WA-LB | 1205Wa 0000002911 | yes |  | m² | Trockenbauarbeiten | Wand | 2x Gipsfaserplatte | WA-LB |  |  | 7.5 | 1205HWa0000002879 | NEW | no | yes | 0 | 0.9 |  | 32 | AllplanAttributes - ash D_Detailverweis: <undefiniert>; Sicherheitsklasse: -; Sonnenschutztyp: Movable; g-Wert: 0,51
Holzständer + Zwischendämmung | H2 Ebene +2 | WA-HD | 1205Wa 0000002913 | yes |  | m³ | Zimmer- und Holzbauarbeiten | Wand | Holzständer + Zwischendämmung | WA-HD |  |  | 7.5 | 1205HWa0000002879 | NEW | no | yes | 0 | 0.9 |  | 32 | AllplanAttributes - ash D_Detailverweis: <undefiniert>; Sicherheitsklasse: -; Sonnenschutztyp: Movable; g-Wert: 0,51; ash W_laufende Nr. Statik: 5 (W 4.0)
Staffel + Zwischendämmung | H2 Ebene +2 | WA-DL | 1205Wa 0000002915 | yes |  | m³ | Zimmer- und Holzbauarbeiten | Wand | Staffel + Zwischendämmung | WA-DL |  |  | 7.5 | 1205HWa0000002879 | NEW | no | yes | 0 | 0.9 |  | 32 | AllplanAttributes - ash D_Detailverweis: <undefiniert>; Sicherheitsklasse: -; Sonnenschutztyp: Movable; g-Wert: 0,51
 | H2 Ebene +2 | WA-LB | 1205Wa 0000002917 | yes | Codetext | m² | Trockenbauarbeiten | Wand | Außenwand 7-Schalig | WA-LB | 0 | A | 7.5 | 1205HWa0000002879 | NEW | no | yes | 0 | 0.9 | no | 32 | no | Codetext | AllplanAttributes - ash D_Detailverweis: <undefiniert>; Sicherheitsklasse: -; Sonnenschutztyp: Movable; g-Wert: 0,51
Konterlattung | H2 Ebene +2 | WA-KL | 1205Wa 0000002919 | yes |  | m² | Zimmer- und Holzbauarbeiten | Wand | Konterlattung | WA-KL |  |  | 7.5 | 1205HWa0000002879 | NEW | no | yes | 0 | 0.9 |  | 32 | AllplanAttributes - ash D_Detailverweis: <undefiniert>; Sicherheitsklasse: -; Sonnenschutztyp: Movable; g-Wert: 0,51
Traglattung | H2 Ebene +2 | WA-TL | 1205Wa 0000002921 | yes |  | m² | Zimmer- und Holzbauarbeiten | Wand | Traglattung | WA-TL |  |  | 7.5 | 1205HWa0000002879 | NEW | no | yes | 0 | 0.9 |  | 32 | AllplanAttributes - ash D_Detailverweis: <undefiniert>; Sicherheitsklasse: -; Sonnenschutztyp: Movable; g-Wert: 0,51
Holzschindel | H2 Ebene +2 | WA-HS | 1205Wa 0000002923 | yes |  | m² | Zimmer- und Holzbauarbeiten | Wand | Holzschindel | WA-HS |  |  | 7.5 | 1205HWa0000002879 | NEW | no | yes | 0 | 0.9 |  | 32 | AllplanAttributes - ash D_Detailverweis: <undefiniert>; Sicherheitsklasse: -; Sonnenschutztyp: Movable; g-Wert: 0,51
 | H2 Ebene +2 | WA-LB | 1205Wa 0000002907 | yes | Codetext | m² | Trockenbauarbeiten | Wand | Außenwand 7-Schalig | WA-LB | 0 | A | 7.5 | 1205HWa0000002845 | NEW | no | yes | 0 | 0.9 | no | - | no | Codetext | AllplanAttributes - ash D_Detailverweis: <undefiniert>; Sicherheitsklasse: -; Sonnenschutztyp: Movable; g-Wert: 0,51
 | H2 Ebene +2 | WA-DL | 1205Wa 0000002903 | yes | Codetext | m³ | Zimmer- und Holzbauarbeiten | Wand | Außenwand 7-Schalig | WA-DL | 0 | A | 7.5 | 1205HWa0000002845 | NEW | no | yes | 0 | 0.9 | no | - | no | Codetext | AllplanAttributes - ash D_Detailverweis: <undefiniert>; Sicherheitsklasse: -; Sonnenschutztyp: Movable; g-Wert: 0,51
 | H2 Ebene +2 | WA-DL | 1205Wa 0000002899 | yes | Codetext | m³ | Zimmer- und Holzbauarbeiten | Wand | Außenwand 7-Schalig | WA-DL | 0 | A | 7.5 | 1205HWa0000002845 | NEW | no | yes | 0 | 0.9 | no | - | no | Codetext | AllplanAttributes - ash D_Detailverweis: <undefiniert>; Sicherheitsklasse: -; Sonnenschutztyp: Movable; g-Wert: 0,51
 | H2 Ebene +2 | WA-LB | 1205Wa 0000002895 | yes | Codetext | m² | Trockenbauarbeiten | Wand | Außenwand 7-Schalig | WA-LB | 0 | A | 7.5 | 1205HWa0000002845 | NEW | no | yes | 0 | 0.9 | no | - | no | Codetext | AllplanAttributes - ash D_Detailverweis: <undefiniert>; Sicherheitsklasse: -; Sonnenschutztyp: Movable; g-Wert: 0,51
 | H2 Ebene +2 | WA-KL | 1205Wa 0000002891 | yes | Codetext | m² | Zimmer- und Holzbauarbeiten | Wand | Außenwand 7-Schalig | WA-KL | 0 | A | 7.5 | 1205HWa0000002845 | NEW | no | yes | 0 | 0.9 | no | - | no | Codetext | AllplanAttributes - ash D_Detailverweis: <undefiniert>; Sicherheitsklasse: -; Sonnenschutztyp: Movable; g-Wert: 0,51
 | H2 Ebene +2 | WA-TL | 1205Wa 0000002887 | yes | Codetext | m² | Zimmer- und Holzbauarbeiten | Wand | Außenwand 7-Schalig | WA-TL | 0 | A | 7.5 | 1205HWa0000002845 | NEW | no | yes | 0 | 0.9 | no | - | no | Codetext | AllplanAttributes - ash D_Detailverweis: <undefiniert>; Sicherheitsklasse: -; Sonnenschutztyp: Movable; g-Wert: 0,51
 | H2 Ebene +2 | WA-HS | 1205Wa 0000002883 | yes | Codetext | m² | Zimmer- und Holzbauarbeiten | Wand | Außenwand 7-Schalig | WA-HS | 0 | A | 7.5 | 1205HWa0000002845 | NEW | no | yes | 0 | 0.9 | no | - | no | Codetext | AllplanAttributes - ash D_Detailverweis: <undefiniert>; Sicherheitsklasse: -; Sonnenschutztyp: Movable; g-Wert: 0,51
 | H2 Ebene +2 | WA-LB | 1205Wa 0000002926 | yes | Codetext | m² | Trockenbauarbeiten | Wand | Außenwand 7-Schalig | WA-LB | 0 | A | 7.5 | 1205HWa0000002909 | NEW | no | yes | 0 | 0.9 | no | 32 | no | Codetext | AllplanAttributes - ash D_Detailverweis: <undefiniert>; Sicherheitsklasse: -; Sonnenschutztyp: Movable; g-Wert: 0,51
 | H2 Ebene +2 | WA-HD | 1205Wa 0000002928 | yes | Codetext | m³ | Zimmer- und Holzbauarbeiten | Wand | Außenwand 7-Schalig | WA-HD | 0 | A | 7.5 | 1205HWa0000002909 | NEW | no | yes | 0 | 0.9 | no | 32 | no | Codetext | AllplanAttributes - ash D_Detailverweis: <undefiniert>; Sicherheitsklasse: -; Sonnenschutztyp: Movable; g-Wert: 0,51; ash W_laufende Nr. Statik: 5 (W 4.0)
 | H2 Ebene +2 | WA-DL | 1205Wa 0000002939 | yes | Codetext | m³ | Zimmer- und Holzbauarbeiten | Wand | Außenwand 7-Schalig | WA-DL | 0 | A | 7.5 | 1205HWa0000002909 | NEW | no | yes | 0 | 0.9 | no | 32 | no | Codetext | AllplanAttributes - ash D_Detailverweis: <undefiniert>; Sicherheitsklasse: -; Sonnenschutztyp: Movable; g-Wert: 0,51
 | H2 Ebene +2 | WA-LB | 1205Wa 0000002937 | yes | Codetext | m² | Trockenbauarbeiten | Wand | Außenwand 7-Schalig | WA-LB | 0 | A | 7.5 | 1205HWa0000002909 | NEW | no | yes | 0 | 0.9 | no | 32 | no | Codetext | AllplanAttributes - ash D_Detailverweis: <undefiniert>; Sicherheitsklasse: -; Sonnenschutztyp: Movable; g-Wert: 0,51
 | H2 Ebene +2 | WA-KL | 1205Wa 0000002935 | yes | Codetext | m² | Zimmer- und Holzbauarbeiten | Wand | Außenwand 7-Schalig | WA-KL | 0 | A | 7.5 | 1205HWa0000002909 | NEW | no | yes | 0 | 0.9 | no | 32 | no | Codetext | AllplanAttributes - ash D_Detailverweis: <undefiniert>; Sicherheitsklasse: -; Sonnenschutztyp: Movable; g-Wert: 0,51
 | H2 Ebene +2 | WA-TL | 1205Wa 0000002933 | yes | Codetext | m² | Zimmer- und Holzbauarbeiten | Wand | Außenwand 7-Schalig | WA-TL | 0 | A | 7.5 | 1205HWa0000002909 | NEW | no | yes | 0 | 0.9 | no | 32 | no | Codetext | AllplanAttributes - ash D_Detailverweis: <undefiniert>; Sicherheitsklasse: -; Sonnenschutztyp: Movable; g-Wert: 0,51
 | H2 Ebene +2 | WA-HS | 1205Wa 0000002931 | yes | Codetext | m² | Zimmer- und Holzbauarbeiten | Wand | Außenwand 7-Schalig | WA-HS | 0 | A | 7.5 | 1205HWa0000002909 | NEW | no | yes | 0 | 0.9 | no | 32 | no | Codetext | AllplanAttributes - ash D_Detailverweis: <undefiniert>; Sicherheitsklasse: -; Sonnenschutztyp: Movable; g-Wert: 0,51
 | H2 Ebene +2 | WA-LB | 1205Wa 0000003057 | yes | Codetext | m² | Trockenbauarbeiten | Wand | Außenwand 7-Schalig | WA-LB | 0 | A | 7.5 | 1205HWa0000002994 | NEW | no | yes | 0 | 0.9 | no | - | no | Codetext | AllplanAttributes - ash D_Detailverweis: <undefiniert>; Sicherheitsklasse: -; Sonnenschutztyp: Movable; g-Wert: 0,51
 | H2 Ebene +2 | WA-HD | 1205Wa 0000003053 | yes | Codetext | m³ | Zimmer- und Holzbauarbeiten | Wand | Außenwand 7-Schalig | WA-HD | 0 | A | 7.5 | 1205HWa0000002994 | NEW | no | yes | 0 | 0.9 | no | - | no | Codetext | AllplanAttributes - ash D_Detailverweis: <undefiniert>; Sicherheitsklasse: -; Sonnenschutztyp: Movable; g-Wert: 0,51; ash W_laufende Nr. Statik: 5 (W 4.0)
 | H2 Ebene +2 | WA-DL | 1205Wa 0000003049 | yes | Codetext | m³ | Zimmer- und Holzbauarbeiten | Wand | Außenwand 7-Schalig | WA-DL | 0 | A | 7.5 | 1205HWa0000002994 | NEW | no | yes | 0 | 0.9 | no | - | no | Codetext | AllplanAttributes - ash D_Detailverweis: <undefiniert>; Sicherheitsklasse: -; Sonnenschutztyp: Movable; g-Wert: 0,51
 | H2 Ebene +2 | WA-LB | 1205Wa 0000003045 | yes | Codetext | m² | Trockenbauarbeiten | Wand | Außenwand 7-Schalig | WA-LB | 0 | A | 7.5 | 1205HWa0000002994 | NEW | no | yes | 0 | 0.9 | no | - | no | Codetext | AllplanAttributes - ash D_Detailverweis: <undefiniert>; Sicherheitsklasse: -; Sonnenschutztyp: Movable; g-Wert: 0,51
 | H2 Ebene +2 | WA-KL | 1205Wa 0000003041 | yes | Codetext | m² | Zimmer- und Holzbauarbeiten | Wand | Außenwand 7-Schalig | WA-KL | 0 | A | 7.5 | 1205HWa0000002994 | NEW | no | yes | 0 | 0.9 | no | - | no | Codetext | AllplanAttributes - ash D_Detailverweis: <undefiniert>; Sicherheitsklasse: -; Sonnenschutztyp: Movable; g-Wert: 0,51
 | H2 Ebene +2 | WA-TL | 1205Wa 0000003037 | yes | Codetext | m² | Zimmer- und Holzbauarbeiten | Wand | Außenwand 7-Schalig | WA-TL | 0 | A | 7.5 | 1205HWa0000002994 | NEW | no | yes | 0 | 0.9 | no | - | no | Codetext | AllplanAttributes - ash D_Detailverweis: <undefiniert>; Sicherheitsklasse: -; Sonnenschutztyp: Movable; g-Wert: 0,51
 | H2 Ebene +2 | WA-HS | 1205Wa 0000003033 | yes | Codetext | m² | Zimmer- und Holzbauarbeiten | Wand | Außenwand 7-Schalig | WA-HS | 0 | A | 7.5 | 1205HWa0000002994 | NEW | no | yes | 0 | 0.9 | no | - | no | Codetext | AllplanAttributes - ash D_Detailverweis: <undefiniert>; Sicherheitsklasse: -; Sonnenschutztyp: Movable; g-Wert: 0,51
 | H2 Ebene +2 | WA-LB | 1205Wa 0000003126 | yes | Codetext | m² | Trockenbauarbeiten | Wand | Außenwand 7-Schalig | WA-LB | 0 | A | 7.5 | 1205HWa0000003028 | NEW | no | yes | 0 | 0.9 | no | 32 | no | Codetext | AllplanAttributes - ash D_Detailverweis: <undefiniert>; Sicherheitsklasse: -; Sonnenschutztyp: Movable; g-Wert: 0,51
 | H2 Ebene +2 | WA-HD | 1205Wa 0000003124 | yes | Codetext | m³ | Zimmer- und Holzbauarbeiten | Wand | Außenwand 7-Schalig | WA-HD | 0 | A | 7.5 | 1205HWa0000003028 | NEW | no | yes | 0 | 0.9 | no | 32 | no | Codetext | AllplanAttributes - ash D_Detailverweis: DT B; ash D_Plannummer: D1851; Sicherheitsklasse: -; Sonnenschutztyp: Movable; g-Wert: 0,51; ash W_laufende Nr. Statik: 5 (W 4.0)
 | H2 Ebene +2 | WA-DL | 1205Wa 0000003122 | yes | Codetext | m³ | Zimmer- und Holzbauarbeiten | Wand | Außenwand 7-Schalig | WA-DL | 0 | A | 7.5 | 1205HWa0000003028 | NEW | no | yes | 0 | 0.9 | no | 32 | no | Codetext | AllplanAttributes - ash D_Detailverweis: <undefiniert>; Sicherheitsklasse: -; Sonnenschutztyp: Movable; g-Wert: 0,51
 | H2 Ebene +2 | WA-LB | 1205Wa 0000003120 | yes | Codetext | m² | Trockenbauarbeiten | Wand | Außenwand 7-Schalig | WA-LB | 0 | A | 7.5 | 1205HWa0000003028 | NEW | no | yes | 0 | 0.9 | no | 32 | no | Codetext | AllplanAttributes - ash D_Detailverweis: <undefiniert>; Sicherheitsklasse: -; Sonnenschutztyp: Movable; g-Wert: 0,51
 | H2 Ebene +2 | WA-KL | 1205Wa 0000003118 | yes | Codetext | m² | Zimmer- und Holzbauarbeiten | Wand | Außenwand 7-Schalig | WA-KL | 0 | A | 7.5 | 1205HWa0000003028 | NEW | no | yes | 0 | 0.9 | no | 32 | no | Codetext | AllplanAttributes - ash D_Detailverweis: <undefiniert>; Sicherheitsklasse: -; Sonnenschutztyp: Movable; g-Wert: 0,51
 | H2 Ebene +2 | WA-TL | 1205Wa 0000003116 | yes | Codetext | m² | Zimmer- und Holzbauarbeiten | Wand | Außenwand 7-Schalig | WA-TL | 0 | A | 7.5 | 1205HWa0000003028 | NEW | no | yes | 0 | 0.9 | no | 32 | no | Codetext | AllplanAttributes - ash D_Detailverweis: <undefiniert>; Sicherheitsklasse: -; Sonnenschutztyp: Movable; g-Wert: 0,51
 | H2 Ebene +2 | WA-HS | 1205Wa 0000003114 | yes | Codetext | m² | Zimmer- und Holzbauarbeiten | Wand | Außenwand 7-Schalig | WA-HS | 0 | A | 7.5 | 1205HWa0000003028 | NEW | no | yes | 0 | 0.9 | no | 32 | no | Codetext | AllplanAttributes - ash D_Detailverweis: <undefiniert>; Sicherheitsklasse: -; Sonnenschutztyp: Movable; g-Wert: 0,51
2x Gipsfaserplatte | H2 Ebene +2 | WA-LB | 1205Wa 0000003128 | yes |  | m² | Trockenbauarbeiten | Wand | 2x Gipsfaserplatte | WA-LB |  |  | 7.5 | 1205HWa0000003029 | NEW | no | yes | 0 | 0.9 |  | 32 | AllplanAttributes - ash D_Detailverweis: <undefiniert>; Sicherheitsklasse: -; Sonnenschutztyp: Movable; g-Wert: 0,51
Holzständer + Zwischendämmung | H2 Ebene +2 | WA-HD | 1205Wa 0000003130 | yes |  | m³ | Zimmer- und Holzbauarbeiten | Wand | Holzständer + Zwischendämmung | WA-HD |  |  | 7.5 | 1205HWa0000003029 | NEW | no | yes | 0 | 0.9 |  | 32 | AllplanAttributes - ash D_Detailverweis: <undefiniert>; Sicherheitsklasse: -; Sonnenschutztyp: Movable; g-Wert: 0,51; ash W_laufende Nr. Statik: 5 (W 4.0)
Staffel + Zwischendämmung | H2 Ebene +2 | WA-DL | 1205Wa 0000003132 | yes |  | m³ | Zimmer- und Holzbauarbeiten | Wand | Staffel + Zwischendämmung | WA-DL |  |  | 7.5 | 1205HWa0000003029 | NEW | no | yes | 0 | 0.9 |  | 32 | AllplanAttributes - ash D_Detailverweis: <undefiniert>; Sicherheitsklasse: -; Sonnenschutztyp: Movable; g-Wert: 0,51
 | H2 Ebene +2 | WA-LB | 1205Wa 0000003134 | yes | Codetext | m² | Trockenbauarbeiten | Wand | Außenwand 7-Schalig | WA-LB | 0 | A | 7.5 | 1205HWa0000003029 | NEW | no | yes | 0 | 0.9 | no | 32 | no | Codetext | AllplanAttributes - ash D_Detailverweis: <undefiniert>; Sicherheitsklasse: -; Sonnenschutztyp: Movable; g-Wert: 0,51
Konterlattung | H2 Ebene +2 | WA-KL | 1205Wa 0000003136 | yes |  | m² | Zimmer- und Holzbauarbeiten | Wand | Konterlattung | WA-KL |  |  | 7.5 | 1205HWa0000003029 | NEW | no | yes | 0 | 0.9 |  | 32 | AllplanAttributes - ash D_Detailverweis: <undefiniert>; Sicherheitsklasse: -; Sonnenschutztyp: Movable; g-Wert: 0,51
Traglattung | H2 Ebene +2 | WA-TL | 1205Wa 0000003138 | yes |  | m² | Zimmer- und Holzbauarbeiten | Wand | Traglattung | WA-TL |  |  | 7.5 | 1205HWa0000003029 | NEW | no | yes | 0 | 0.9 |  | 32 | AllplanAttributes - ash D_Detailverweis: <undefiniert>; Sicherheitsklasse: -; Sonnenschutztyp: Movable; g-Wert: 0,51
Holzschindel | H2 Ebene +2 | WA-HS | 1205Wa 0000003140 | yes |  | m² | Zimmer- und Holzbauarbeiten | Wand | Holzschindel | WA-HS |  |  | 7.5 | 1205HWa0000003029 | NEW | no | yes | 0 | 0.9 |  | 32 | AllplanAttributes - ash D_Detailverweis: <undefiniert>; Sicherheitsklasse: -; Sonnenschutztyp: Movable; g-Wert: 0,51
 | H2 Ebene +2 | WA-LB | 1205Wa 0000003947 | yes | Codetext | m² | Trockenbauarbeiten | Wand | Außenwand 7-Schalig | WA-LB | 0 | A | 7.5 | 1205HWa0000003164 | NEW | no | yes | 0 | 0.9 | no | 32 | no | Codetext | AllplanAttributes - ash D_Detailverweis: <undefiniert>; Sicherheitsklasse: -; Sonnenschutztyp: Movable; g-Wert: 0,51
 | H2 Ebene +2 | WA-DL | 1205Wa 0000003957 | yes | Codetext | m³ | Zimmer- und Holzbauarbeiten | Wand | Außenwand 7-Schalig | WA-DL | 0 | A | 7.5 | 1205HWa0000003164 | NEW | no | yes | 0 | 0.9 | no | 32 | no | Codetext | AllplanAttributes - ash D_Detailverweis: DT D; ash D_Plannummer: D1851; Sicherheitsklasse: -; Sonnenschutztyp: Movable; g-Wert: 0,51; ash W_laufende Nr. Statik: 2 (W 2.0/ 2.1/ 2.2)
 | H2 Ebene +2 | WA-DL | 1205Wa 0000003966 | yes | Codetext | m³ | Zimmer- und Holzbauarbeiten | Wand | Außenwand 7-Schalig | WA-DL | 0 | A | 7.5 | 1205HWa0000003164 | NEW | no | yes | 0 | 0.9 | no | 32 | no | Codetext | AllplanAttributes - ash D_Detailverweis: <undefiniert>; Sicherheitsklasse: -; Sonnenschutztyp: Movable; g-Wert: 0,51
 | H2 Ebene +2 | WA-LB | 1205Wa 0000003976 | yes | Codetext | m² | Trockenbauarbeiten | Wand | Außenwand 7-Schalig | WA-LB | 0 | A | 7.5 | 1205HWa0000003164 | NEW | no | yes | 0 | 0.9 | no | 32 | no | Codetext | AllplanAttributes - ash D_Detailverweis: <undefiniert>; Sicherheitsklasse: -; Sonnenschutztyp: Movable; g-Wert: 0,51
 | H2 Ebene +2 | WA-KL | 1205Wa 0000003986 | yes | Codetext | m² | Zimmer- und Holzbauarbeiten | Wand | Außenwand 7-Schalig | WA-KL | 0 | A | 7.5 | 1205HWa0000003164 | NEW | no | yes | 0 | 0.9 | no | 32 | no | Codetext | AllplanAttributes - ash D_Detailverweis: <undefiniert>; Sicherheitsklasse: -; Sonnenschutztyp: Movable; g-Wert: 0,51
 | H2 Ebene +2 | WA-TL | 1205Wa 0000003996 | yes | Codetext | m² | Zimmer- und Holzbauarbeiten | Wand | Außenwand 7-Schalig | WA-TL | 0 | A | 7.5 | 1205HWa0000003164 | NEW | no | yes | 0 | 0.9 | no | 32 | no | Codetext | AllplanAttributes - ash D_Detailverweis: <undefiniert>; Sicherheitsklasse: -; Sonnenschutztyp: Movable; g-Wert: 0,51
 | H2 Ebene +2 | WA-HS | 1205Wa 0000004006 | yes | Codetext | m² | Zimmer- und Holzbauarbeiten | Wand | Außenwand 7-Schalig | WA-HS | 0 | A | 7.5 | 1205HWa0000003164 | NEW | no | yes | 0 | 0.9 | no | 32 | no | Codetext | AllplanAttributes - ash D_Detailverweis: <undefiniert>; Sicherheitsklasse: -; Sonnenschutztyp: Movable; g-Wert: 0,51
 | H2 Ebene +2 | WA-LB | 1205Wa 0000004443 | yes | Codetext | m² | Trockenbauarbeiten | Wand | Außenwand 7-Schalig | WA-LB | 0 | A | 7.5 | 1205HWa0000004384 | NEW | no | yes | 0 | 0.9 | no | 32 | no | Codetext | AllplanAttributes - ash D_Detailverweis: <undefiniert>; Sicherheitsklasse: -; Sonnenschutztyp: Movable; g-Wert: 0,51
 | H2 Ebene +2 | WA-DL | 1205Wa 0000004441 | yes | Codetext | m³ | Zimmer- und Holzbauarbeiten | Wand | Außenwand 7-Schalig | WA-DL | 0 | A | 7.5 | 1205HWa0000004384 | NEW | no | yes | 0 | 0.9 | no | 32 | no | Codetext | AllplanAttributes - ash D_Detailverweis: DT D; ash D_Plannummer: D1851; Sicherheitsklasse: -; Sonnenschutztyp: Movable; g-Wert: 0,51; ash W_laufende Nr. Statik: 2 (W 2.0/ 2.1/ 2.2)
 | H2 Ebene +2 | WA-DL | 1205Wa 0000004439 | yes | Codetext | m³ | Zimmer- und Holzbauarbeiten | Wand | Außenwand 7-Schalig | WA-DL | 0 | A | 7.5 | 1205HWa0000004384 | NEW | no | yes | 0 | 0.9 | no | 32 | no | Codetext | AllplanAttributes - ash D_Detailverweis: <undefiniert>; Sicherheitsklasse: -; Sonnenschutztyp: Movable; g-Wert: 0,51
 | H2 Ebene +2 | WA-LB | 1205Wa 0000004437 | yes | Codetext | m² | Trockenbauarbeiten | Wand | Außenwand 7-Schalig | WA-LB | 0 | A | 7.5 | 1205HWa0000004384 | NEW | no | yes | 0 | 0.9 | no | 32 | no | Codetext | AllplanAttributes - ash D_Detailverweis: <undefiniert>; Sicherheitsklasse: -; Sonnenschutztyp: Movable; g-Wert: 0,51
 | H2 Ebene +2 | WA-KL | 1205Wa 0000004435 | yes | Codetext | m² | Zimmer- und Holzbauarbeiten | Wand | Außenwand 7-Schalig | WA-KL | 0 | A | 7.5 | 1205HWa0000004384 | NEW | no | yes | 0 | 0.9 | no | 32 | no | Codetext | AllplanAttributes - ash D_Detailverweis: <undefiniert>; Sicherheitsklasse: -; Sonnenschutztyp: Movable; g-Wert: 0,51
 | H2 Ebene +2 | WA-TL | 1205Wa 0000004433 | yes | Codetext | m² | Zimmer- und Holzbauarbeiten | Wand | Außenwand 7-Schalig | WA-TL | 0 | A | 7.5 | 1205HWa0000004384 | NEW | no | yes | 0 | 0.9 | no | 32 | no | Codetext | AllplanAttributes - ash D_Detailverweis: <undefiniert>; Sicherheitsklasse: -; Sonnenschutztyp: Movable; g-Wert: 0,51
 | H2 Ebene +2 | WA-HS | 1205Wa 0000004431 | yes | Codetext | m² | Zimmer- und Holzbauarbeiten | Wand | Außenwand 7-Schalig | WA-HS | 0 | A | 7.5 | 1205HWa0000004384 | NEW | no | yes | 0 | 0.9 | no | 32 | no | Codetext | AllplanAttributes - ash D_Detailverweis: <undefiniert>; Sicherheitsklasse: -; Sonnenschutztyp: Movable; g-Wert: 0,51
2x Gipsfaserplatte | H2 Ebene +2 | WA-LB | 1205Wa 0000004471 | yes |  | m² | Trockenbauarbeiten | Wand | 2x Gipsfaserplatte | WA-LB |  |  | 7.5 | 1205HWa0000004382 | NEW | no | yes | 0 | 0.9 |  | 32 | AllplanAttributes - ash D_Detailverweis: <undefiniert>; Sicherheitsklasse: -; Sonnenschutztyp: Movable; g-Wert: 0,51
Holzständer + Zwischendämmung | H2 Ebene +2 | WA-DL | 1205Wa 0000004469 | yes |  | m³ | Zimmer- und Holzbauarbeiten | Wand | Holzständer + Zwischendämmung | WA-DL |  |  | 7.5 | 1205HWa0000004382 | NEW | no | yes | 0 | 0.9 |  | 32 | AllplanAttributes - ash D_Detailverweis: <undefiniert>; Sicherheitsklasse: -; Sonnenschutztyp: Movable; g-Wert: 0,51; ash W_laufende Nr. Statik: 2 (W 2.0/ 2.1/ 2.2)
Staffel + Zwischendämmung | H2 Ebene +2 | WA-DL | 1205Wa 0000004467 | yes |  | m³ | Zimmer- und Holzbauarbeiten | Wand | Staffel + Zwischendämmung | WA-DL |  |  | 7.5 | 1205HWa0000004382 | NEW | no | yes | 0 | 0.9 |  | 32 | AllplanAttributes - ash D_Detailverweis: <undefiniert>; Sicherheitsklasse: -; Sonnenschutztyp: Movable; g-Wert: 0,51
 | H2 Ebene +2 | WA-LB | 1205Wa 0000004465 | yes | Codetext | m² | Trockenbauarbeiten | Wand | Außenwand 7-Schalig | WA-LB | 0 | A | 7.5 | 1205HWa0000004382 | NEW | no | yes | 0 | 0.9 | no | 32 | no | Codetext | AllplanAttributes - ash D_Detailverweis: <undefiniert>; Sicherheitsklasse: -; Sonnenschutztyp: Movable; g-Wert: 0,51
Konterlattung | H2 Ebene +2 | WA-KL | 1205Wa 0000004463 | yes |  | m² | Zimmer- und Holzbauarbeiten | Wand | Konterlattung | WA-KL |  |  | 7.5 | 1205HWa0000004382 | NEW | no | yes | 0 | 0.9 |  | 32 | AllplanAttributes - ash D_Detailverweis: <undefiniert>; Sicherheitsklasse: -; Sonnenschutztyp: Movable; g-Wert: 0,51
Traglattung | H2 Ebene +2 | WA-TL | 1205Wa 0000004461 | yes |  | m² | Zimmer- und Holzbauarbeiten | Wand | Traglattung | WA-TL |  |  | 7.5 | 1205HWa0000004382 | NEW | no | yes | 0 | 0.9 |  | 32 | AllplanAttributes - ash D_Detailverweis: <undefiniert>; Sicherheitsklasse: -; Sonnenschutztyp: Movable; g-Wert: 0,51
Holzschindel | H2 Ebene +2 | WA-HS | 1205Wa 0000004459 | yes |  | m² | Zimmer- und Holzbauarbeiten | Wand | Holzschindel | WA-HS |  |  | 7.5 | 1205HWa0000004382 | NEW | no | yes | 0 | 0.9 |  | 32 | AllplanAttributes - ash D_Detailverweis: <undefiniert>; Sicherheitsklasse: -; Sonnenschutztyp: Movable; g-Wert: 0,51
 | H2 Ebene +2 | WA-LB | 1205Wa 0000004803 | yes | Codetext | m² | Trockenbauarbeiten | Wand | Außenwand 7-Schalig | WA-LB | 0 | A | 7.5 | 1205HWa0000003165 | NEW | no | yes | 0 | 0.9 | no | 32 | no | Codetext | AllplanAttributes - ash D_Detailverweis: <undefiniert>; Sicherheitsklasse: -; Sonnenschutztyp: Movable; g-Wert: 0,51
 | H2 Ebene +2 | WA-DL | 1205Wa 0000004805 | yes | Codetext | m³ | Zimmer- und Holzbauarbeiten | Wand | Außenwand 7-Schalig | WA-DL | 0 | A | 7.5 | 1205HWa0000003165 | NEW | no | yes | 0 | 0.9 | no | 32 | no | Codetext | AllplanAttributes - ash D_Detailverweis: <undefiniert>; Sicherheitsklasse: -; Sonnenschutztyp: Movable; g-Wert: 0,51; ash W_laufende Nr. Statik: 2 (W 2.0/ 2.1/ 2.2)
 | H2 Ebene +2 | WA-DL | 1205Wa 0000004807 | yes | Codetext | m³ | Zimmer- und Holzbauarbeiten | Wand | Außenwand 7-Schalig | WA-DL | 0 | A | 7.5 | 1205HWa0000003165 | NEW | no | yes | 0 | 0.9 | no | 32 | no | Codetext | AllplanAttributes - ash D_Detailverweis: <undefiniert>; Sicherheitsklasse: -; Sonnenschutztyp: Movable; g-Wert: 0,51
 | H2 Ebene +2 | WA-LB | 1205Wa 0000004809 | yes | Codetext | m² | Trockenbauarbeiten | Wand | Außenwand 7-Schalig | WA-LB | 0 | A | 7.5 | 1205HWa0000003165 | NEW | no | yes | 0 | 0.9 | no | 32 | no | Codetext | AllplanAttributes - ash D_Detailverweis: <undefiniert>; Sicherheitsklasse: -; Sonnenschutztyp: Movable; g-Wert: 0,51
 | H2 Ebene +2 | WA-KL | 1205Wa 0000004811 | yes | Codetext | m² | Zimmer- und Holzbauarbeiten | Wand | Außenwand 7-Schalig | WA-KL | 0 | A | 7.5 | 1205HWa0000003165 | NEW | no | yes | 0 | 0.9 | no | 32 | no | Codetext | AllplanAttributes - ash D_Detailverweis: <undefiniert>; Sicherheitsklasse: -; Sonnenschutztyp: Movable; g-Wert: 0,51
 | H2 Ebene +2 | WA-TL | 1205Wa 0000004813 | yes | Codetext | m² | Zimmer- und Holzbauarbeiten | Wand | Außenwand 7-Schalig | WA-TL | 0 | A | 7.5 | 1205HWa0000003165 | NEW | no | yes | 0 | 0.9 | no | 32 | no | Codetext | AllplanAttributes - ash D_Detailverweis: <undefiniert>; Sicherheitsklasse: -; Sonnenschutztyp: Movable; g-Wert: 0,51
 | H2 Ebene +2 | WA-HS | 1205Wa 0000004815 | yes | Codetext | m² | Zimmer- und Holzbauarbeiten | Wand | Außenwand 7-Schalig | WA-HS | 0 | A | 7.5 | 1205HWa0000003165 | NEW | no | yes | 0 | 0.9 | no | 32 | no | Codetext | AllplanAttributes - ash D_Detailverweis: <undefiniert>; Sicherheitsklasse: -; Sonnenschutztyp: Movable; g-Wert: 0,51
 | H2 Ebene +2 | WA-LB | 1205Wa 0000004406 | yes | Codetext | m² | Trockenbauarbeiten | Wand | Außenwand 7-Schalig | WA-LB | 0 | A | 7.5 | 1205HWa0000004287 | NEW | no | yes | 0 | 0.9 | no | - | no | Codetext | AllplanAttributes - ash D_Detailverweis: <undefiniert>; Sicherheitsklasse: -; Sonnenschutztyp: Movable; g-Wert: 0,51
 | H2 Ebene +2 | WA-DL | 1205Wa 0000004410 | yes | Codetext | m³ | Zimmer- und Holzbauarbeiten | Wand | Außenwand 7-Schalig | WA-DL | 0 | A | 7.5 | 1205HWa0000004287 | NEW | no | yes | 0 | 0.9 | no | - | no | Codetext | AllplanAttributes - ash D_Detailverweis: DT D; ash D_Plannummer: D1851; Sicherheitsklasse: -; Sonnenschutztyp: Movable; g-Wert: 0,51; ash W_laufende Nr. Statik: 2 (W 2.0/ 2.1/ 2.2)
 | H2 Ebene +2 | WA-DL | 1205Wa 0000004402 | yes | Codetext | m³ | Zimmer- und Holzbauarbeiten | Wand | Außenwand 7-Schalig | WA-DL | 0 | A | 7.5 | 1205HWa0000004287 | NEW | no | yes | 0 | 0.9 | no | - | no | Codetext | AllplanAttributes - ash D_Detailverweis: <undefiniert>; Sicherheitsklasse: -; Sonnenschutztyp: Movable; g-Wert: 0,51
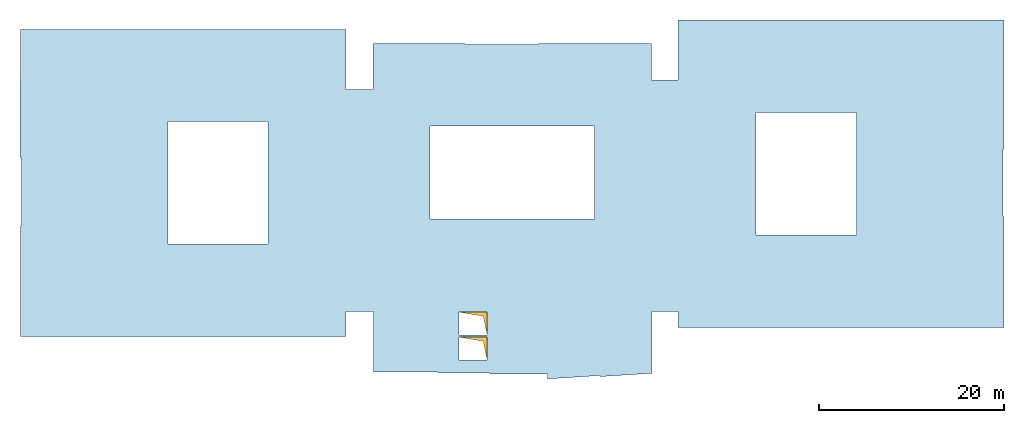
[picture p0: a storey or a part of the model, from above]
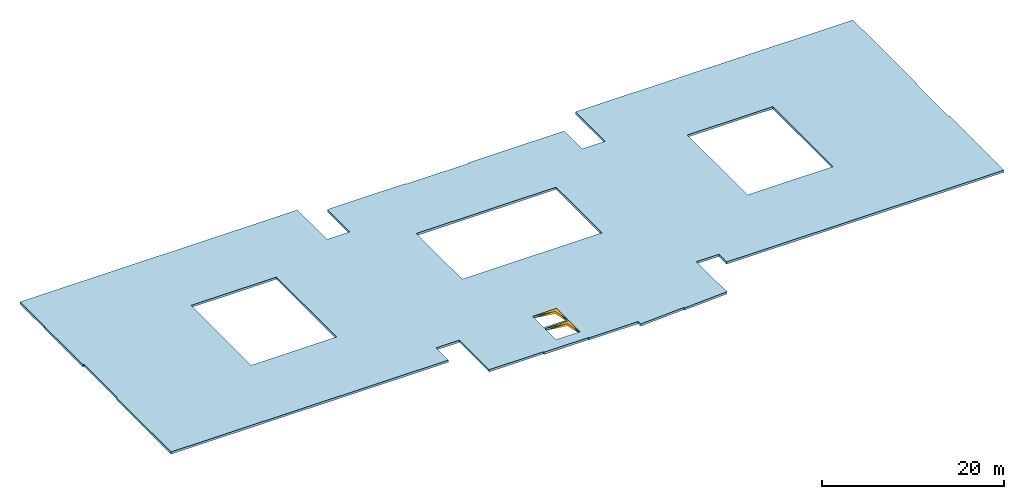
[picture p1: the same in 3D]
Properties of the parts of a building model (IFC4), part 50 of 80

# IfcWall (6826)
Name | In | Material | Allright_Bauteil_ID | 2D Interaktion | Codetext | Abrechnungsart | Gewerk | Objektname | Bezeichnung | AllplanAttributes, Material | Typ = SurfaceSpreadOfFlame | Brandschutzklasse | OKFF | P_ID | Status | LoadBearing | IsExternal | FireRating | ThermalTransmittance (W/K/m2) | Combustible | AcousticRating | Compartmentation | Reference
 | H2 Ebene +2 | WA-LB | 1205Wa 0000004398 | yes | Codetext | m² | Trockenbauarbeiten | Wand | Außenwand 7-Schalig | WA-LB | 0 | A | 7.5 | 1205HWa0000004287 | NEW | no | yes | 0 | 0.9 | no | - | no | Codetext | AllplanAttributes - ash D_Detailverweis: <undefiniert>; Sicherheitsklasse: -; Sonnenschutztyp: Movable; g-Wert: 0,51
 | H2 Ebene +2 | WA-KL | 1205Wa 0000004394 | yes | Codetext | m² | Zimmer- und Holzbauarbeiten | Wand | Außenwand 7-Schalig | WA-KL | 0 | A | 7.5 | 1205HWa0000004287 | NEW | no | yes | 0 | 0.9 | no | - | no | Codetext | AllplanAttributes - ash D_Detailverweis: <undefiniert>; Sicherheitsklasse: -; Sonnenschutztyp: Movable; g-Wert: 0,51
 | H2 Ebene +2 | WA-TL | 1205Wa 0000004390 | yes | Codetext | m² | Zimmer- und Holzbauarbeiten | Wand | Außenwand 7-Schalig | WA-TL | 0 | A | 7.5 | 1205HWa0000004287 | NEW | no | yes | 0 | 0.9 | no | - | no | Codetext | AllplanAttributes - ash D_Detailverweis: <undefiniert>; Sicherheitsklasse: -; Sonnenschutztyp: Movable; g-Wert: 0,51
 | H2 Ebene +2 | WA-HS | 1205Wa 0000004416 | yes | Codetext | m² | Zimmer- und Holzbauarbeiten | Wand | Außenwand 7-Schalig | WA-HS | 0 | A | 7.5 | 1205HWa0000004287 | NEW | no | yes | 0 | 0.9 | no | - | no | Codetext | AllplanAttributes - ash D_Detailverweis: <undefiniert>; Sicherheitsklasse: -; Sonnenschutztyp: Movable; g-Wert: 0,51
2x Gipsfaserplatte | H2 Ebene +2 | WA-LB | 1205Wa 0000004352 | yes |  | m² | Trockenbauarbeiten | Wand | 2x Gipsfaserplatte | WA-LB |  |  | 7.5 | 1205HWa0000004338 | NEW | no | yes | 0 | 0.9 |  | 32 | AllplanAttributes - ash D_Detailverweis: <undefiniert>; Sicherheitsklasse: -; Sonnenschutztyp: Movable; g-Wert: 0,51
Holzständer + Zwischendämmung | H2 Ebene +2 | WA-DL | 1205Wa 0000004350 | yes |  | m³ | Zimmer- und Holzbauarbeiten | Wand | Holzständer + Zwischendämmung | WA-DL |  |  | 7.5 | 1205HWa0000004338 | NEW | no | yes | 0 | 0.9 |  | 32 | AllplanAttributes - ash D_Detailverweis: <undefiniert>; Sicherheitsklasse: -; Sonnenschutztyp: Movable; g-Wert: 0,51; ash W_laufende Nr. Statik: 2 (W 2.0/ 2.1/ 2.2)
Staffel + Zwischendämmung | H2 Ebene +2 | WA-DL | 1205Wa 0000004348 | yes |  | m³ | Zimmer- und Holzbauarbeiten | Wand | Staffel + Zwischendämmung | WA-DL |  |  | 7.5 | 1205HWa0000004338 | NEW | no | yes | 0 | 0.9 |  | 32 | AllplanAttributes - ash D_Detailverweis: <undefiniert>; Sicherheitsklasse: -; Sonnenschutztyp: Movable; g-Wert: 0,51
 | H2 Ebene +2 | WA-LB | 1205Wa 0000004346 | yes | Codetext | m² | Trockenbauarbeiten | Wand | Außenwand 7-Schalig | WA-LB | 0 | A | 7.5 | 1205HWa0000004338 | NEW | no | yes | 0 | 0.9 | no | 32 | no | Codetext | AllplanAttributes - ash D_Detailverweis: <undefiniert>; Sicherheitsklasse: -; Sonnenschutztyp: Movable; g-Wert: 0,51
Konterlattung | H2 Ebene +2 | WA-KL | 1205Wa 0000004344 | yes |  | m² | Zimmer- und Holzbauarbeiten | Wand | Konterlattung | WA-KL |  |  | 7.5 | 1205HWa0000004338 | NEW | no | yes | 0 | 0.9 |  | 32 | AllplanAttributes - ash D_Detailverweis: <undefiniert>; Sicherheitsklasse: -; Sonnenschutztyp: Movable; g-Wert: 0,51
Traglattung | H2 Ebene +2 | WA-TL | 1205Wa 0000004342 | yes |  | m² | Zimmer- und Holzbauarbeiten | Wand | Traglattung | WA-TL |  |  | 7.5 | 1205HWa0000004338 | NEW | no | yes | 0 | 0.9 |  | 32 | AllplanAttributes - ash D_Detailverweis: <undefiniert>; Sicherheitsklasse: -; Sonnenschutztyp: Movable; g-Wert: 0,51
Holzschindel | H2 Ebene +2 | WA-HS | 1205Wa 0000004340 | yes |  | m² | Zimmer- und Holzbauarbeiten | Wand | Holzschindel | WA-HS |  |  | 7.5 | 1205HWa0000004338 | NEW | no | yes | 0 | 0.9 |  | 32 | AllplanAttributes - ash D_Detailverweis: <undefiniert>; Sicherheitsklasse: -; Sonnenschutztyp: Movable; g-Wert: 0,51
 | H2 Ebene +2 | WA-LB | 1205Wa 0000004611 | yes | Codetext | m² | Trockenbauarbeiten | Wand | Außenwand 7-Schalig | WA-LB | 0 | A | 7.5 | 1205HWa0000004228 | NEW | no | yes | 0 | 0.9 | no | 32 | no | Codetext | AllplanAttributes - ash D_Detailverweis: <undefiniert>; Sicherheitsklasse: -; Sonnenschutztyp: Movable; g-Wert: 0,51
 | H2 Ebene +2 | WA-DL | 1205Wa 0000004607 | yes | Codetext | m³ | Zimmer- und Holzbauarbeiten | Wand | Außenwand 7-Schalig | WA-DL | 0 | A | 7.5 | 1205HWa0000004228 | NEW | no | yes | 0 | 0.9 | no | 32 | no | Codetext | AllplanAttributes - ash D_Detailverweis: DT D; ash D_Plannummer: D1851; Sicherheitsklasse: -; Sonnenschutztyp: Movable; g-Wert: 0,51; ash W_laufende Nr. Statik: 2 (W 2.0/ 2.1/ 2.2)
 | H2 Ebene +2 | WA-DL | 1205Wa 0000004603 | yes | Codetext | m³ | Zimmer- und Holzbauarbeiten | Wand | Außenwand 7-Schalig | WA-DL | 0 | A | 7.5 | 1205HWa0000004228 | NEW | no | yes | 0 | 0.9 | no | 32 | no | Codetext | AllplanAttributes - ash D_Detailverweis: <undefiniert>; Sicherheitsklasse: -; Sonnenschutztyp: Movable; g-Wert: 0,51
 | H2 Ebene +2 | WA-LB | 1205Wa 0000004599 | yes | Codetext | m² | Trockenbauarbeiten | Wand | Außenwand 7-Schalig | WA-LB | 0 | A | 7.5 | 1205HWa0000004228 | NEW | no | yes | 0 | 0.9 | no | 32 | no | Codetext | AllplanAttributes - ash D_Detailverweis: <undefiniert>; Sicherheitsklasse: -; Sonnenschutztyp: Movable; g-Wert: 0,51
 | H2 Ebene +2 | WA-KL | 1205Wa 0000004595 | yes | Codetext | m² | Zimmer- und Holzbauarbeiten | Wand | Außenwand 7-Schalig | WA-KL | 0 | A | 7.5 | 1205HWa0000004228 | NEW | no | yes | 0 | 0.9 | no | 32 | no | Codetext | AllplanAttributes - ash D_Detailverweis: <undefiniert>; Sicherheitsklasse: -; Sonnenschutztyp: Movable; g-Wert: 0,51
 | H2 Ebene +2 | WA-TL | 1205Wa 0000004591 | yes | Codetext | m² | Zimmer- und Holzbauarbeiten | Wand | Außenwand 7-Schalig | WA-TL | 0 | A | 7.5 | 1205HWa0000004228 | NEW | no | yes | 0 | 0.9 | no | 32 | no | Codetext | AllplanAttributes - ash D_Detailverweis: <undefiniert>; Sicherheitsklasse: -; Sonnenschutztyp: Movable; g-Wert: 0,51
 | H2 Ebene +2 | WA-HS | 1205Wa 0000004587 | yes | Codetext | m² | Zimmer- und Holzbauarbeiten | Wand | Außenwand 7-Schalig | WA-HS | 0 | A | 7.5 | 1205HWa0000004228 | NEW | no | yes | 0 | 0.9 | no | 32 | no | Codetext | AllplanAttributes - ash D_Detailverweis: <undefiniert>; Sicherheitsklasse: -; Sonnenschutztyp: Movable; g-Wert: 0,51
 | H2 Ebene +2 | WA-LB | 1205Wa 0000004689 | yes | Codetext | m² | Trockenbauarbeiten | Wand | Außenwand 7-Schalig | WA-LB | 0 | A | 7.5 | 1205HWa0000004249 | NEW | no | yes | 0 | 0.9 | no | - | no | Codetext | AllplanAttributes - ash D_Detailverweis: <undefiniert>; Sicherheitsklasse: -; Sonnenschutztyp: Movable; g-Wert: 0,51
 | H2 Ebene +2 | WA-DL | 1205Wa 0000004693 | yes | Codetext | m³ | Zimmer- und Holzbauarbeiten | Wand | Außenwand 7-Schalig | WA-DL | 0 | A | 7.5 | 1205HWa0000004249 | NEW | no | yes | 0 | 0.9 | no | - | no | Codetext | AllplanAttributes - ash D_Detailverweis: <undefiniert>; Sicherheitsklasse: -; Sonnenschutztyp: Movable; g-Wert: 0,51; ash W_laufende Nr. Statik: 2 (W 2.0/ 2.1/ 2.2)
 | H2 Ebene +2 | WA-DL | 1205Wa 0000004697 | yes | Codetext | m³ | Zimmer- und Holzbauarbeiten | Wand | Außenwand 7-Schalig | WA-DL | 0 | A | 7.5 | 1205HWa0000004249 | NEW | no | yes | 0 | 0.9 | no | - | no | Codetext | AllplanAttributes - ash D_Detailverweis: <undefiniert>; Sicherheitsklasse: -; Sonnenschutztyp: Movable; g-Wert: 0,51
 | H2 Ebene +2 | WA-LB | 1205Wa 0000004701 | yes | Codetext | m² | Trockenbauarbeiten | Wand | Außenwand 7-Schalig | WA-LB | 0 | A | 7.5 | 1205HWa0000004249 | NEW | no | yes | 0 | 0.9 | no | - | no | Codetext | AllplanAttributes - ash D_Detailverweis: <undefiniert>; Sicherheitsklasse: -; Sonnenschutztyp: Movable; g-Wert: 0,51
 | H2 Ebene +2 | WA-KL | 1205Wa 0000004705 | yes | Codetext | m² | Zimmer- und Holzbauarbeiten | Wand | Außenwand 7-Schalig | WA-KL | 0 | A | 7.5 | 1205HWa0000004249 | NEW | no | yes | 0 | 0.9 | no | - | no | Codetext | AllplanAttributes - ash D_Detailverweis: <undefiniert>; Sicherheitsklasse: -; Sonnenschutztyp: Movable; g-Wert: 0,51
 | H2 Ebene +2 | WA-TL | 1205Wa 0000004709 | yes | Codetext | m² | Zimmer- und Holzbauarbeiten | Wand | Außenwand 7-Schalig | WA-TL | 0 | A | 7.5 | 1205HWa0000004249 | NEW | no | yes | 0 | 0.9 | no | - | no | Codetext | AllplanAttributes - ash D_Detailverweis: <undefiniert>; Sicherheitsklasse: -; Sonnenschutztyp: Movable; g-Wert: 0,51
 | H2 Ebene +2 | WA-HS | 1205Wa 0000004713 | yes | Codetext | m² | Zimmer- und Holzbauarbeiten | Wand | Außenwand 7-Schalig | WA-HS | 0 | A | 7.5 | 1205HWa0000004249 | NEW | no | yes | 0 | 0.9 | no | 32 | no | Codetext | AllplanAttributes - ash D_Detailverweis: <undefiniert>; Sicherheitsklasse: -; Sonnenschutztyp: Movable; g-Wert: 0,51
 | H2 Ebene +2 | WA-LB | 1205Wa 0000004655 | yes | Codetext | m² | Trockenbauarbeiten | Wand | Außenwand 7-Schalig | WA-LB | 0 | A | 7.5 | 1205HWa0000004247 | NEW | no | yes | 0 | 0.9 | no | 32 | no | Codetext | AllplanAttributes - ash D_Detailverweis: <undefiniert>; Sicherheitsklasse: -; Sonnenschutztyp: Movable; g-Wert: 0,51
 | H2 Ebene +2 | WA-DL | 1205Wa 0000004651 | yes | Codetext | m³ | Zimmer- und Holzbauarbeiten | Wand | Außenwand 7-Schalig | WA-DL | 0 | A | 7.5 | 1205HWa0000004247 | NEW | no | yes | 0 | 0.9 | no | 32 | no | Codetext | AllplanAttributes - ash D_Detailverweis: <undefiniert>; Sicherheitsklasse: -; Sonnenschutztyp: Movable; g-Wert: 0,51; ash W_laufende Nr. Statik: 2 (W 2.0/ 2.1/ 2.2)
 | H2 Ebene +2 | WA-DL | 1205Wa 0000004647 | yes | Codetext | m³ | Zimmer- und Holzbauarbeiten | Wand | Außenwand 7-Schalig | WA-DL | 0 | A | 7.5 | 1205HWa0000004247 | NEW | no | yes | 0 | 0.9 | no | 32 | no | Codetext | AllplanAttributes - ash D_Detailverweis: <undefiniert>; Sicherheitsklasse: -; Sonnenschutztyp: Movable; g-Wert: 0,51
 | H2 Ebene +2 | WA-LB | 1205Wa 0000004643 | yes | Codetext | m² | Trockenbauarbeiten | Wand | Außenwand 7-Schalig | WA-LB | 0 | A | 7.5 | 1205HWa0000004247 | NEW | no | yes | 0 | 0.9 | no | 32 | no | Codetext | AllplanAttributes - ash D_Detailverweis: <undefiniert>; Sicherheitsklasse: -; Sonnenschutztyp: Movable; g-Wert: 0,51
 | H2 Ebene +2 | WA-KL | 1205Wa 0000004639 | yes | Codetext | m² | Zimmer- und Holzbauarbeiten | Wand | Außenwand 7-Schalig | WA-KL | 0 | A | 7.5 | 1205HWa0000004247 | NEW | no | yes | 0 | 0.9 | no | 32 | no | Codetext | AllplanAttributes - ash D_Detailverweis: <undefiniert>; Sicherheitsklasse: -; Sonnenschutztyp: Movable; g-Wert: 0,51
 | H2 Ebene +2 | WA-TL | 1205Wa 0000004635 | yes | Codetext | m² | Zimmer- und Holzbauarbeiten | Wand | Außenwand 7-Schalig | WA-TL | 0 | A | 7.5 | 1205HWa0000004247 | NEW | no | yes | 0 | 0.9 | no | 32 | no | Codetext | AllplanAttributes - ash D_Detailverweis: <undefiniert>; Sicherheitsklasse: -; Sonnenschutztyp: Movable; g-Wert: 0,51
 | H2 Ebene +2 | WA-HS | 1205Wa 0000004631 | yes | Codetext | m² | Zimmer- und Holzbauarbeiten | Wand | Außenwand 7-Schalig | WA-HS | 0 | A | 7.5 | 1205HWa0000004247 | NEW | no | yes | 0 | 0.9 | no | 32 | no | Codetext | AllplanAttributes - ash D_Detailverweis: <undefiniert>; Sicherheitsklasse: -; Sonnenschutztyp: Movable; g-Wert: 0,51
2x Gipsfaserplatte | H2 Ebene +2 | WA-LB | 1205Wa 0000004583 | yes |  | m² | Trockenbauarbeiten | Wand | 2x Gipsfaserplatte | WA-LB |  |  | 7.5 | 1205HWa0000004569 | NEW | no | yes | 0 | 0.9 |  | 32 | AllplanAttributes - ash D_Detailverweis: <undefiniert>; Sicherheitsklasse: -; Sonnenschutztyp: Movable; g-Wert: 0,51
Holzständer + Zwischendämmung | H2 Ebene +2 | WA-DL | 1205Wa 0000004581 | yes |  | m³ | Zimmer- und Holzbauarbeiten | Wand | Holzständer + Zwischendämmung | WA-DL |  |  | 7.5 | 1205HWa0000004569 | NEW | no | yes | 0 | 0.9 |  | 32 | AllplanAttributes - ash D_Detailverweis: <undefiniert>; Sicherheitsklasse: -; Sonnenschutztyp: Movable; g-Wert: 0,51; ash W_laufende Nr. Statik: 2 (W 2.0/ 2.1/ 2.2)
Staffel + Zwischendämmung | H2 Ebene +2 | WA-DL | 1205Wa 0000004579 | yes |  | m³ | Zimmer- und Holzbauarbeiten | Wand | Staffel + Zwischendämmung | WA-DL |  |  | 7.5 | 1205HWa0000004569 | NEW | no | yes | 0 | 0.9 |  | 32 | AllplanAttributes - ash D_Detailverweis: <undefiniert>; Sicherheitsklasse: -; Sonnenschutztyp: Movable; g-Wert: 0,51
 | H2 Ebene +2 | WA-LB | 1205Wa 0000004577 | yes | Codetext | m² | Trockenbauarbeiten | Wand | Außenwand 7-Schalig | WA-LB | 0 | A | 7.5 | 1205HWa0000004569 | NEW | no | yes | 0 | 0.9 | no | 32 | no | Codetext | AllplanAttributes - ash D_Detailverweis: <undefiniert>; Sicherheitsklasse: -; Sonnenschutztyp: Movable; g-Wert: 0,51
Konterlattung | H2 Ebene +2 | WA-KL | 1205Wa 0000004575 | yes |  | m² | Zimmer- und Holzbauarbeiten | Wand | Konterlattung | WA-KL |  |  | 7.5 | 1205HWa0000004569 | NEW | no | yes | 0 | 0.9 |  | 32 | AllplanAttributes - ash D_Detailverweis: <undefiniert>; Sicherheitsklasse: -; Sonnenschutztyp: Movable; g-Wert: 0,51
Traglattung | H2 Ebene +2 | WA-TL | 1205Wa 0000004573 | yes |  | m² | Zimmer- und Holzbauarbeiten | Wand | Traglattung | WA-TL |  |  | 7.5 | 1205HWa0000004569 | NEW | no | yes | 0 | 0.9 |  | 32 | AllplanAttributes - ash D_Detailverweis: <undefiniert>; Sicherheitsklasse: -; Sonnenschutztyp: Movable; g-Wert: 0,51
Holzschindel | H2 Ebene +2 | WA-HS | 1205Wa 0000004571 | yes |  | m² | Zimmer- und Holzbauarbeiten | Wand | Holzschindel | WA-HS |  |  | 7.5 | 1205HWa0000004569 | NEW | no | yes | 0 | 0.9 |  | 32 | AllplanAttributes - ash D_Detailverweis: <undefiniert>; Sicherheitsklasse: -; Sonnenschutztyp: Movable; g-Wert: 0,51
2x Gipsfaserplatte | H2 Ebene +2 | WA-LB | 1205Wa 0000004627 | yes |  | m² | Trockenbauarbeiten | Wand | 2x Gipsfaserplatte | WA-LB |  |  | 7.5 | 1205HWa0000004613 | NEW | no | yes | 0 | 0.9 |  | 32 | AllplanAttributes - ash D_Detailverweis: <undefiniert>; Sicherheitsklasse: -; Sonnenschutztyp: Movable; g-Wert: 0,51
Holzständer + Zwischendämmung | H2 Ebene +2 | WA-DL | 1205Wa 0000004625 | yes |  | m³ | Zimmer- und Holzbauarbeiten | Wand | Holzständer + Zwischendämmung | WA-DL |  |  | 7.5 | 1205HWa0000004613 | NEW | no | yes | 0 | 0.9 |  | 32 | AllplanAttributes - ash D_Detailverweis: <undefiniert>; Sicherheitsklasse: -; Sonnenschutztyp: Movable; g-Wert: 0,51; ash W_laufende Nr. Statik: 2 (W 2.0/ 2.1/ 2.2)
Staffel + Zwischendämmung | H2 Ebene +2 | WA-DL | 1205Wa 0000004623 | yes |  | m³ | Zimmer- und Holzbauarbeiten | Wand | Staffel + Zwischendämmung | WA-DL |  |  | 7.5 | 1205HWa0000004613 | NEW | no | yes | 0 | 0.9 |  | 32 | AllplanAttributes - ash D_Detailverweis: <undefiniert>; Sicherheitsklasse: -; Sonnenschutztyp: Movable; g-Wert: 0,51
 | H2 Ebene +2 | WA-LB | 1205Wa 0000004621 | yes | Codetext | m² | Trockenbauarbeiten | Wand | Außenwand 7-Schalig | WA-LB | 0 | A | 7.5 | 1205HWa0000004613 | NEW | no | yes | 0 | 0.9 | no | 32 | no | Codetext | AllplanAttributes - ash D_Detailverweis: <undefiniert>; Sicherheitsklasse: -; Sonnenschutztyp: Movable; g-Wert: 0,51
Konterlattung | H2 Ebene +2 | WA-KL | 1205Wa 0000004619 | yes |  | m² | Zimmer- und Holzbauarbeiten | Wand | Konterlattung | WA-KL |  |  | 7.5 | 1205HWa0000004613 | NEW | no | yes | 0 | 0.9 |  | 32 | AllplanAttributes - ash D_Detailverweis: <undefiniert>; Sicherheitsklasse: -; Sonnenschutztyp: Movable; g-Wert: 0,51
Traglattung | H2 Ebene +2 | WA-TL | 1205Wa 0000004617 | yes |  | m² | Zimmer- und Holzbauarbeiten | Wand | Traglattung | WA-TL |  |  | 7.5 | 1205HWa0000004613 | NEW | no | yes | 0 | 0.9 |  | 32 | AllplanAttributes - ash D_Detailverweis: <undefiniert>; Sicherheitsklasse: -; Sonnenschutztyp: Movable; g-Wert: 0,51
Holzschindel | H2 Ebene +2 | WA-HS | 1205Wa 0000004615 | yes |  | m² | Zimmer- und Holzbauarbeiten | Wand | Holzschindel | WA-HS |  |  | 7.5 | 1205HWa0000004613 | NEW | no | yes | 0 | 0.9 |  | 32 | AllplanAttributes - ash D_Detailverweis: <undefiniert>; Sicherheitsklasse: -; Sonnenschutztyp: Movable; g-Wert: 0,51
2x Gipsfaserplatte | H2 Ebene +2 | WA-LB | 1205Wa 0000004481 | yes |  | m² | Trockenbauarbeiten | Wand | 2x Gipsfaserplatte | WA-LB |  |  | 7.5 | 1205HWa0000004472 | NEW | no | yes | 0 | 0.9 |  | 32 | AllplanAttributes - ash D_Detailverweis: <undefiniert>; Sicherheitsklasse: -; Sonnenschutztyp: Movable; g-Wert: 0,51
Holzständer + Zwischendämmung | H2 Ebene +2 | WA-DL | 1205Wa 0000004483 | yes |  | m³ | Zimmer- und Holzbauarbeiten | Wand | Holzständer + Zwischendämmung | WA-DL |  |  | 7.5 | 1205HWa0000004472 | NEW | no | yes | 0 | 0.9 |  | 32 | AllplanAttributes - ash D_Detailverweis: <undefiniert>; Sicherheitsklasse: -; Sonnenschutztyp: Movable; g-Wert: 0,51; ash W_laufende Nr. Statik: 2 (W 2.0/ 2.1/ 2.2)
Staffel + Zwischendämmung | H2 Ebene +2 | WA-DL | 1205Wa 0000004485 | yes |  | m³ | Zimmer- und Holzbauarbeiten | Wand | Staffel + Zwischendämmung | WA-DL |  |  | 7.5 | 1205HWa0000004472 | NEW | no | yes | 0 | 0.9 |  | 32 | AllplanAttributes - ash D_Detailverweis: <undefiniert>; Sicherheitsklasse: -; Sonnenschutztyp: Movable; g-Wert: 0,51
 | H2 Ebene +2 | WA-LB | 1205Wa 0000004487 | yes | Codetext | m² | Trockenbauarbeiten | Wand | Außenwand 7-Schalig | WA-LB | 0 | A | 7.5 | 1205HWa0000004472 | NEW | no | yes | 0 | 0.9 | no | 32 | no | Codetext | AllplanAttributes - ash D_Detailverweis: <undefiniert>; Sicherheitsklasse: -; Sonnenschutztyp: Movable; g-Wert: 0,51
Konterlattung | H2 Ebene +2 | WA-KL | 1205Wa 0000004489 | yes |  | m² | Zimmer- und Holzbauarbeiten | Wand | Konterlattung | WA-KL |  |  | 7.5 | 1205HWa0000004472 | NEW | no | yes | 0 | 0.9 |  | 32 | AllplanAttributes - ash D_Detailverweis: <undefiniert>; Sicherheitsklasse: -; Sonnenschutztyp: Movable; g-Wert: 0,51
Traglattung | H2 Ebene +2 | WA-TL | 1205Wa 0000004491 | yes |  | m² | Zimmer- und Holzbauarbeiten | Wand | Traglattung | WA-TL |  |  | 7.5 | 1205HWa0000004472 | NEW | no | yes | 0 | 0.9 |  | 32 | AllplanAttributes - ash D_Detailverweis: <undefiniert>; Sicherheitsklasse: -; Sonnenschutztyp: Movable; g-Wert: 0,51
Holzschindel | H2 Ebene +2 | WA-HS | 1205Wa 0000004493 | yes |  | m² | Zimmer- und Holzbauarbeiten | Wand | Holzschindel | WA-HS |  |  | 7.5 | 1205HWa0000004472 | NEW | no | yes | 0 | 0.9 |  | 32 | AllplanAttributes - ash D_Detailverweis: <undefiniert>; Sicherheitsklasse: -; Sonnenschutztyp: Movable; g-Wert: 0,51
2x Gipsfaserplatte | H2 Ebene +2 | WA-LB | 1205Wa 0000004187 | yes |  | m² | Trockenbauarbeiten | Wand | 2x Gipsfaserplatte | WA-LB |  |  | 7.5 | 1205HWa0000003281 | NEW | no | yes | 0 | 0.9 |  | 32 | AllplanAttributes - ash D_Detailverweis: <undefiniert>; Sicherheitsklasse: -; Sonnenschutztyp: Movable; g-Wert: 0,51
Holzständer + Zwischendämmung | H2 Ebene +2 | WA-DL | 1205Wa 0000004189 | yes |  | m³ | Zimmer- und Holzbauarbeiten | Wand | Holzständer + Zwischendämmung | WA-DL |  |  | 7.5 | 1205HWa0000003281 | NEW | no | yes | 0 | 0.9 |  | 32 | AllplanAttributes - ash D_Detailverweis: <undefiniert>; Sicherheitsklasse: -; Sonnenschutztyp: Movable; g-Wert: 0,51; ash W_laufende Nr. Statik: 2 (W 2.0/ 2.1/ 2.2)
Staffel + Zwischendämmung | H2 Ebene +2 | WA-DL | 1205Wa 0000004191 | yes |  | m³ | Zimmer- und Holzbauarbeiten | Wand | Staffel + Zwischendämmung | WA-DL |  |  | 7.5 | 1205HWa0000003281 | NEW | no | yes | 0 | 0.9 |  | 32 | AllplanAttributes - ash D_Detailverweis: <undefiniert>; Sicherheitsklasse: -; Sonnenschutztyp: Movable; g-Wert: 0,51
 | H2 Ebene +2 | WA-LB | 1205Wa 0000004193 | yes | Codetext | m² | Trockenbauarbeiten | Wand | Außenwand 7-Schalig | WA-LB | 0 | A | 7.5 | 1205HWa0000003281 | NEW | no | yes | 0 | 0.9 | no | 32 | no | Codetext | AllplanAttributes - ash D_Detailverweis: <undefiniert>; Sicherheitsklasse: -; Sonnenschutztyp: Movable; g-Wert: 0,51
Konterlattung | H2 Ebene +2 | WA-KL | 1205Wa 0000004195 | yes |  | m² | Zimmer- und Holzbauarbeiten | Wand | Konterlattung | WA-KL |  |  | 7.5 | 1205HWa0000003281 | NEW | no | yes | 0 | 0.9 |  | 32 | AllplanAttributes - ash D_Detailverweis: <undefiniert>; Sicherheitsklasse: -; Sonnenschutztyp: Movable; g-Wert: 0,51
Traglattung | H2 Ebene +2 | WA-TL | 1205Wa 0000004197 | yes |  | m² | Zimmer- und Holzbauarbeiten | Wand | Traglattung | WA-TL |  |  | 7.5 | 1205HWa0000003281 | NEW | no | yes | 0 | 0.9 |  | 32 | AllplanAttributes - ash D_Detailverweis: <undefiniert>; Sicherheitsklasse: -; Sonnenschutztyp: Movable; g-Wert: 0,51
Holzschindel | H2 Ebene +2 | WA-HS | 1205Wa 0000004199 | yes |  | m² | Zimmer- und Holzbauarbeiten | Wand | Holzschindel | WA-HS |  |  | 7.5 | 1205HWa0000003281 | NEW | no | yes | 0 | 0.9 |  | 32 | AllplanAttributes - ash D_Detailverweis: <undefiniert>; Sicherheitsklasse: -; Sonnenschutztyp: Movable; g-Wert: 0,51
 | H2 Ebene +2 | WA-LB | 1205Wa 0000004893 | yes | Codetext | m² | Trockenbauarbeiten | Wand | Außenwand 7-Schalig | WA-LB | 0 | A | 7.5 | 1205HWa0000004161 | NEW | no | yes | 0 | 0.9 | no | 32 | no | Codetext | AllplanAttributes - ash D_Detailverweis: <undefiniert>; Sicherheitsklasse: -; Sonnenschutztyp: Movable; g-Wert: 0,51
 | H2 Ebene +2 | WA-DL | 1205Wa 0000004889 | yes | Codetext | m³ | Zimmer- und Holzbauarbeiten | Wand | Außenwand 7-Schalig | WA-DL | 0 | A | 7.5 | 1205HWa0000004161 | NEW | no | yes | 0 | 0.9 | no | 32 | no | Codetext | AllplanAttributes - ash D_Detailverweis: <undefiniert>; Sicherheitsklasse: -; Sonnenschutztyp: Movable; g-Wert: 0,51; ash W_laufende Nr. Statik: 2 (W 2.0/ 2.1/ 2.2)
 | H2 Ebene +2 | WA-DL | 1205Wa 0000004885 | yes | Codetext | m³ | Zimmer- und Holzbauarbeiten | Wand | Außenwand 7-Schalig | WA-DL | 0 | A | 7.5 | 1205HWa0000004161 | NEW | no | yes | 0 | 0.9 | no | 32 | no | Codetext | AllplanAttributes - ash D_Detailverweis: <undefiniert>; Sicherheitsklasse: -; Sonnenschutztyp: Movable; g-Wert: 0,51
 | H2 Ebene +2 | WA-LB | 1205Wa 0000004881 | yes | Codetext | m² | Trockenbauarbeiten | Wand | Außenwand 7-Schalig | WA-LB | 0 | A | 7.5 | 1205HWa0000004161 | NEW | no | yes | 0 | 0.9 | no | 32 | no | Codetext | AllplanAttributes - ash D_Detailverweis: <undefiniert>; Sicherheitsklasse: -; Sonnenschutztyp: Movable; g-Wert: 0,51
 | H2 Ebene +2 | WA-KL | 1205Wa 0000004877 | yes | Codetext | m² | Zimmer- und Holzbauarbeiten | Wand | Außenwand 7-Schalig | WA-KL | 0 | A | 7.5 | 1205HWa0000004161 | NEW | no | yes | 0 | 0.9 | no | 32 | no | Codetext | AllplanAttributes - ash D_Detailverweis: <undefiniert>; Sicherheitsklasse: -; Sonnenschutztyp: Movable; g-Wert: 0,51
 | H2 Ebene +2 | WA-TL | 1205Wa 0000004873 | yes | Codetext | m² | Zimmer- und Holzbauarbeiten | Wand | Außenwand 7-Schalig | WA-TL | 0 | A | 7.5 | 1205HWa0000004161 | NEW | no | yes | 0 | 0.9 | no | 32 | no | Codetext | AllplanAttributes - ash D_Detailverweis: <undefiniert>; Sicherheitsklasse: -; Sonnenschutztyp: Movable; g-Wert: 0,51
 | H2 Ebene +2 | WA-HS | 1205Wa 0000004869 | yes | Codetext | m² | Zimmer- und Holzbauarbeiten | Wand | Außenwand 7-Schalig | WA-HS | 0 | A | 7.5 | 1205HWa0000004161 | NEW | no | yes | 0 | 0.9 | no | 32 | no | Codetext | AllplanAttributes - ash D_Detailverweis: <undefiniert>; Sicherheitsklasse: -; Sonnenschutztyp: Movable; g-Wert: 0,51
2x Gipsfaserplatte | H2 Ebene +2 | WA-LB | 1205Wa 0000004830 | yes |  | m² | Trockenbauarbeiten | Wand | 2x Gipsfaserplatte | WA-LB |  |  | 7.5 | 1205HWa0000004816 | NEW | no | yes | 0 | 0.9 |  | 32 | AllplanAttributes - ash D_Detailverweis: <undefiniert>; Sicherheitsklasse: -; Sonnenschutztyp: Movable; g-Wert: 0,51
Holzständer + Zwischendämmung | H2 Ebene +2 | WA-DL | 1205Wa 0000004828 | yes |  | m³ | Zimmer- und Holzbauarbeiten | Wand | Holzständer + Zwischendämmung | WA-DL |  |  | 7.5 | 1205HWa0000004816 | NEW | no | yes | 0 | 0.9 |  | 32 | AllplanAttributes - ash D_Detailverweis: <undefiniert>; Sicherheitsklasse: -; Sonnenschutztyp: Movable; g-Wert: 0,51; ash W_laufende Nr. Statik: 2 (W 2.0/ 2.1/ 2.2)
Staffel + Zwischendämmung | H2 Ebene +2 | WA-DL | 1205Wa 0000004826 | yes |  | m³ | Zimmer- und Holzbauarbeiten | Wand | Staffel + Zwischendämmung | WA-DL |  |  | 7.5 | 1205HWa0000004816 | NEW | no | yes | 0 | 0.9 |  | 32 | AllplanAttributes - ash D_Detailverweis: <undefiniert>; Sicherheitsklasse: -; Sonnenschutztyp: Movable; g-Wert: 0,51
 | H2 Ebene +2 | WA-LB | 1205Wa 0000004824 | yes | Codetext | m² | Trockenbauarbeiten | Wand | Außenwand 7-Schalig | WA-LB | 0 | A | 7.5 | 1205HWa0000004816 | NEW | no | yes | 0 | 0.9 | no | 32 | no | Codetext | AllplanAttributes - ash D_Detailverweis: <undefiniert>; Sicherheitsklasse: -; Sonnenschutztyp: Movable; g-Wert: 0,51
Konterlattung | H2 Ebene +2 | WA-KL | 1205Wa 0000004822 | yes |  | m² | Zimmer- und Holzbauarbeiten | Wand | Konterlattung | WA-KL |  |  | 7.5 | 1205HWa0000004816 | NEW | no | yes | 0 | 0.9 |  | 32 | AllplanAttributes - ash D_Detailverweis: <undefiniert>; Sicherheitsklasse: -; Sonnenschutztyp: Movable; g-Wert: 0,51
Traglattung | H2 Ebene +2 | WA-TL | 1205Wa 0000004820 | yes |  | m² | Zimmer- und Holzbauarbeiten | Wand | Traglattung | WA-TL |  |  | 7.5 | 1205HWa0000004816 | NEW | no | yes | 0 | 0.9 |  | 32 | AllplanAttributes - ash D_Detailverweis: <undefiniert>; Sicherheitsklasse: -; Sonnenschutztyp: Movable; g-Wert: 0,51
Holzschindel | H2 Ebene +2 | WA-HS | 1205Wa 0000004818 | yes |  | m² | Zimmer- und Holzbauarbeiten | Wand | Holzschindel | WA-HS |  |  | 7.5 | 1205HWa0000004816 | NEW | no | yes | 0 | 0.9 |  | 32 | AllplanAttributes - ash D_Detailverweis: <undefiniert>; Sicherheitsklasse: -; Sonnenschutztyp: Movable; g-Wert: 0,51
 | H2 Ebene +2 | WA-LB | 1205Wa 0000004509 | yes | Codetext | m² | Trockenbauarbeiten | Wand | Außenwand 7-Schalig | WA-LB | 0 | A | 7.5 | 1205HWa0000004474 | NEW | no | yes | 0 | 0.9 | no | 32 | no | Codetext | AllplanAttributes - ash D_Detailverweis: <undefiniert>; Sicherheitsklasse: -; Sonnenschutztyp: Movable; g-Wert: 0,51
 | H2 Ebene +2 | WA-DL | 1205Wa 0000004511 | yes | Codetext | m³ | Zimmer- und Holzbauarbeiten | Wand | Außenwand 7-Schalig | WA-DL | 0 | A | 7.5 | 1205HWa0000004474 | NEW | no | yes | 0 | 0.9 | no | 32 | no | Codetext | AllplanAttributes - ash D_Detailverweis: DT D; ash D_Plannummer: D1851; Sicherheitsklasse: -; Sonnenschutztyp: Movable; g-Wert: 0,51; ash W_laufende Nr. Statik: 2 (W 2.0/ 2.1/ 2.2)
 | H2 Ebene +2 | WA-DL | 1205Wa 0000004513 | yes | Codetext | m³ | Zimmer- und Holzbauarbeiten | Wand | Außenwand 7-Schalig | WA-DL | 0 | A | 7.5 | 1205HWa0000004474 | NEW | no | yes | 0 | 0.9 | no | 32 | no | Codetext | AllplanAttributes - ash D_Detailverweis: <undefiniert>; Sicherheitsklasse: -; Sonnenschutztyp: Movable; g-Wert: 0,51
 | H2 Ebene +2 | WA-LB | 1205Wa 0000004515 | yes | Codetext | m² | Trockenbauarbeiten | Wand | Außenwand 7-Schalig | WA-LB | 0 | A | 7.5 | 1205HWa0000004474 | NEW | no | yes | 0 | 0.9 | no | 32 | no | Codetext | AllplanAttributes - ash D_Detailverweis: <undefiniert>; Sicherheitsklasse: -; Sonnenschutztyp: Movable; g-Wert: 0,51
 | H2 Ebene +2 | WA-KL | 1205Wa 0000004517 | yes | Codetext | m² | Zimmer- und Holzbauarbeiten | Wand | Außenwand 7-Schalig | WA-KL | 0 | A | 7.5 | 1205HWa0000004474 | NEW | no | yes | 0 | 0.9 | no | 32 | no | Codetext | AllplanAttributes - ash D_Detailverweis: <undefiniert>; Sicherheitsklasse: -; Sonnenschutztyp: Movable; g-Wert: 0,51
 | H2 Ebene +2 | WA-TL | 1205Wa 0000004519 | yes | Codetext | m² | Zimmer- und Holzbauarbeiten | Wand | Außenwand 7-Schalig | WA-TL | 0 | A | 7.5 | 1205HWa0000004474 | NEW | no | yes | 0 | 0.9 | no | 32 | no | Codetext | AllplanAttributes - ash D_Detailverweis: <undefiniert>; Sicherheitsklasse: -; Sonnenschutztyp: Movable; g-Wert: 0,51
 | H2 Ebene +2 | WA-HS | 1205Wa 0000004521 | yes | Codetext | m² | Zimmer- und Holzbauarbeiten | Wand | Außenwand 7-Schalig | WA-HS | 0 | A | 7.5 | 1205HWa0000004474 | NEW | no | yes | 0 | 0.9 | no | 32 | no | Codetext | AllplanAttributes - ash D_Detailverweis: <undefiniert>; Sicherheitsklasse: -; Sonnenschutztyp: Movable; g-Wert: 0,51
 | H2 Ebene +2 | WA-LB | 1205Wa 0000005133 | yes | Codetext | m² | Trockenbauarbeiten | Wand | Außenwand 7-Schalig | WA-LB | 0 | A | 7.5 | 1205HWa0000003250 | NEW | no | yes | 0 | 0.9 | no | 32 | no | Codetext | AllplanAttributes - ash D_Detailverweis: <undefiniert>; Sicherheitsklasse: -; Sonnenschutztyp: Movable; g-Wert: 0,51
 | H2 Ebene +2 | WA-DL | 1205Wa 0000005124 | yes | Codetext | m³ | Zimmer- und Holzbauarbeiten | Wand | Außenwand 7-Schalig | WA-DL | 0 | A | 7.5 | 1205HWa0000003250 | NEW | no | yes | 0 | 0.9 | no | 32 | no | Codetext | AllplanAttributes - ash D_Detailverweis: DT D; ash D_Plannummer: D1851; Sicherheitsklasse: -; Sonnenschutztyp: Movable; g-Wert: 0,51; ash W_laufende Nr. Statik: 2 (W 2.0/ 2.1/ 2.2)
 | H2 Ebene +2 | WA-DL | 1205Wa 0000005115 | yes | Codetext | m³ | Zimmer- und Holzbauarbeiten | Wand | Außenwand 7-Schalig | WA-DL | 0 | A | 7.5 | 1205HWa0000003250 | NEW | no | yes | 0 | 0.9 | no | 32 | no | Codetext | AllplanAttributes - ash D_Detailverweis: <undefiniert>; Sicherheitsklasse: -; Sonnenschutztyp: Movable; g-Wert: 0,51
 | H2 Ebene +2 | WA-LB | 1205Wa 0000005106 | yes | Codetext | m² | Trockenbauarbeiten | Wand | Außenwand 7-Schalig | WA-LB | 0 | A | 7.5 | 1205HWa0000003250 | NEW | no | yes | 0 | 0.9 | no | 32 | no | Codetext | AllplanAttributes - ash D_Detailverweis: <undefiniert>; Sicherheitsklasse: -; Sonnenschutztyp: Movable; g-Wert: 0,51
 | H2 Ebene +2 | WA-KL | 1205Wa 0000005097 | yes | Codetext | m² | Zimmer- und Holzbauarbeiten | Wand | Außenwand 7-Schalig | WA-KL | 0 | A | 7.5 | 1205HWa0000003250 | NEW | no | yes | 0 | 0.9 | no | 32 | no | Codetext | AllplanAttributes - ash D_Detailverweis: <undefiniert>; Sicherheitsklasse: -; Sonnenschutztyp: Movable; g-Wert: 0,51
 | H2 Ebene +2 | WA-TL | 1205Wa 0000005088 | yes | Codetext | m² | Zimmer- und Holzbauarbeiten | Wand | Außenwand 7-Schalig | WA-TL | 0 | A | 7.5 | 1205HWa0000003250 | NEW | no | yes | 0 | 0.9 | no | 32 | no | Codetext | AllplanAttributes - ash D_Detailverweis: <undefiniert>; Sicherheitsklasse: -; Sonnenschutztyp: Movable; g-Wert: 0,51
 | H2 Ebene +2 | WA-HS | 1205Wa 0000005079 | yes | Codetext | m² | Zimmer- und Holzbauarbeiten | Wand | Außenwand 7-Schalig | WA-HS | 0 | A | 7.5 | 1205HWa0000003250 | NEW | no | yes | 0 | 0.9 | no | 32 | no | Codetext | AllplanAttributes - ash D_Detailverweis: <undefiniert>; Sicherheitsklasse: -; Sonnenschutztyp: Movable; g-Wert: 0,51
 | H2 Ebene +2 | WA-STB | 1205Wa 0000002371 | yes |  | m² | Zimmer- und Holzbauarbeiten | Wand | Außenwand 2-Schalig | WA-STB |  |  | 7.5 | 1205HWa0000002217 | NEW | no |  | 0 | 0.9 |  | 32 | AllplanAttributes - ash D_Detailverweis: <undefiniert>; Sicherheitsklasse: -; Sonnenschutztyp: Movable; g-Wert: 0,51
 | H2 Ebene +2 | WA-DL | 1205Wa 0000002367 | yes |  | m³ | Zimmer- und Holzbauarbeiten | Wand | Außenwand 2-Schalig | WA-DL |  |  | 7.5 | 1205HWa0000002217 | NEW | no |  | 0 | 0.9 |  | 32 | AllplanAttributes - ash D_Detailverweis: <undefiniert>; Sicherheitsklasse: -; Sonnenschutztyp: Movable; g-Wert: 0,51
 | H2 Ebene +2 | WA-LB | 1205Wa 0000002365 | yes | Codetext | m² | Trockenbauarbeiten | Wand | Außenwand 2-Schalig | WA-LB | 0 | A | 7.5 | 1205HWa0000002217 | NEW | no | yes | 0 | 0.9 | no | 32 | no | Codetext | AllplanAttributes - ash D_Detailverweis: <undefiniert>; Sicherheitsklasse: -; Sonnenschutztyp: Movable; g-Wert: 0,51
 | H2 Ebene +2 | WA-TL | 1205Wa 0000002363 | yes |  | m² | Zimmer- und Holzbauarbeiten | Wand | Außenwand 2-Schalig | WA-TL |  |  | 7.5 | 1205HWa0000002217 | NEW | no |  | 0 | 0.9 |  | 32 | AllplanAttributes - ash D_Detailverweis: <undefiniert>; Sicherheitsklasse: -; Sonnenschutztyp: Movable; g-Wert: 0,51
Traglattung | H2 Ebene +2 | WA-TL | 1205Wa 0000002361 | yes |  | m² | Zimmer- und Holzbauarbeiten | Wand | Traglattung | WA-TL |  |  | 7.5 | 1205HWa0000002217 | NEW | no | yes | 0 | 0.9 |  | 32 | AllplanAttributes - ash D_Detailverweis: <undefiniert>; Sicherheitsklasse: -; Sonnenschutztyp: Movable; g-Wert: 0,51
 | H2 Ebene +2 | WA-HS | 1205Wa 0000093365 | yes |  | m² | Zimmer- und Holzbauarbeiten | Wand | Außenwand 2-Schalig | WA-HS |  |  | 7.5 | 1205HWa0000002217 | NEW | no |  | 0 | 0.9 |  | 32 | AllplanAttributes - ash D_Detailverweis: <undefiniert>; Sicherheitsklasse: -; Sonnenschutztyp: Movable; g-Wert: 0,51
 | H2 Ebene +2 | WA-STB | 1205Wa 0000002335 | yes |  | m² | Zimmer- und Holzbauarbeiten | Wand | Außenwand 2-Schalig | WA-STB |  |  | 7.5 | 1205HWa0000002256 | NEW | no |  | 0 | 0.9 |  | 32 | AllplanAttributes - ash D_Detailverweis: <undefiniert>; Sicherheitsklasse: -; Sonnenschutztyp: Movable; g-Wert: 0,51
 | H2 Ebene +2 | WA-DL | 1205Wa 0000002341 | yes |  | m³ | Zimmer- und Holzbauarbeiten | Wand | Außenwand 2-Schalig | WA-DL |  |  | 7.5 | 1205HWa0000002256 | NEW | no |  | 0 | 0.9 |  | 32 | AllplanAttributes - ash D_Detailverweis: <undefiniert>; Sicherheitsklasse: -; Sonnenschutztyp: Movable; g-Wert: 0,51
 | H2 Ebene +2 | WA-LB | 1205Wa 0000002347 | yes | Codetext | m² | Trockenbauarbeiten | Wand | Außenwand 2-Schalig | WA-LB | 0 | A | 7.5 | 1205HWa0000002256 | NEW | no | yes | 0 | 0.9 | no | 32 | no | Codetext | AllplanAttributes - ash D_Detailverweis: <undefiniert>; Sicherheitsklasse: -; Sonnenschutztyp: Movable; g-Wert: 0,51
 | H2 Ebene +2 | WA-TL | 1205Wa 0000002353 | yes |  | m² | Zimmer- und Holzbauarbeiten | Wand | Außenwand 2-Schalig | WA-TL |  |  | 7.5 | 1205HWa0000002256 | NEW | no |  | 0 | 0.9 |  | 32 | AllplanAttributes - ash D_Detailverweis: <undefiniert>; Sicherheitsklasse: -; Sonnenschutztyp: Movable; g-Wert: 0,51
Traglattung | H2 Ebene +2 | WA-TL | 1205Wa 0000002359 | yes |  | m² | Zimmer- und Holzbauarbeiten | Wand | Traglattung | WA-TL |  |  | 7.5 | 1205HWa0000002256 | NEW | no | yes | 0 | 0.9 |  | 32 | AllplanAttributes - ash D_Detailverweis: <undefiniert>; Sicherheitsklasse: -; Sonnenschutztyp: Movable; g-Wert: 0,51
 | H2 Ebene +2 | WA-HS | 1205Wa 0000092760 | yes |  | m² | Zimmer- und Holzbauarbeiten | Wand | Außenwand 2-Schalig | WA-HS |  |  | 7.5 | 1205HWa0000002256 | NEW | no |  | 0 | 0.9 |  | 32 | AllplanAttributes - ash D_Detailverweis: <undefiniert>; Sicherheitsklasse: -; Sonnenschutztyp: Movable; g-Wert: 0,51
 | H2 Ebene +2 | WA-STB | 1205Wa 0000002369 | yes |  | m² | Zimmer- und Holzbauarbeiten | Wand | Außenwand 2-Schalig | WA-STB |  |  | 7.5 | 1205HWa0000002254 | NEW | no |  | 0 | 0.9 |  | 32 | AllplanAttributes - ash D_Detailverweis: <undefiniert>; Sicherheitsklasse: -; Sonnenschutztyp: Movable; g-Wert: 0,51
 | H2 Ebene +2 | WA-DL | 1205Wa 0000002399 | yes |  | m³ | Zimmer- und Holzbauarbeiten | Wand | Außenwand 2-Schalig | WA-DL |  |  | 7.5 | 1205HWa0000002254 | NEW | no |  | 0 | 0.9 |  | 32 | AllplanAttributes - ash D_Detailverweis: <undefiniert>; Sicherheitsklasse: -; Sonnenschutztyp: Movable; g-Wert: 0,51
 | H2 Ebene +2 | WA-LB | 1205Wa 0000002401 | yes | Codetext | m² | Trockenbauarbeiten | Wand | Außenwand 2-Schalig | WA-LB | 0 | A | 7.5 | 1205HWa0000002254 | NEW | no | yes | 0 | 0.9 | no | 32 | no | Codetext | AllplanAttributes - ash D_Detailverweis: <undefiniert>; Sicherheitsklasse: -; Sonnenschutztyp: Movable; g-Wert: 0,51
 | H2 Ebene +2 | WA-TL | 1205Wa 0000002403 | yes |  | m² | Zimmer- und Holzbauarbeiten | Wand | Außenwand 2-Schalig | WA-TL |  |  | 7.5 | 1205HWa0000002254 | NEW | no |  | 0 | 0.9 |  | 32 | AllplanAttributes - ash D_Detailverweis: <undefiniert>; Sicherheitsklasse: -; Sonnenschutztyp: Movable; g-Wert: 0,51
Traglattung | H2 Ebene +2 | WA-TL | 1205Wa 0000002405 | yes |  | m² | Zimmer- und Holzbauarbeiten | Wand | Traglattung | WA-TL |  |  | 7.5 | 1205HWa0000002254 | NEW | no | yes | 0 | 0.9 |  | 32 | AllplanAttributes - ash D_Detailverweis: <undefiniert>; Sicherheitsklasse: -; Sonnenschutztyp: Movable; g-Wert: 0,51
 | H2 Ebene +2 | WA-HS | 1205Wa 0000092659 | yes |  | m² | Zimmer- und Holzbauarbeiten | Wand | Außenwand 2-Schalig | WA-HS |  |  | 7.5 | 1205HWa0000002254 | NEW | no |  | 0 | 0.9 |  | 32 | AllplanAttributes - ash D_Detailverweis: <undefiniert>; Sicherheitsklasse: -; Sonnenschutztyp: Movable; g-Wert: 0,51
 | H2 Ebene +2 | WA-STB | 1205Wa 0000003016 | yes |  | m² | Zimmer- und Holzbauarbeiten | Wand | Außenwand 2-Schalig | WA-STB |  |  | 7.5 | 1205HWa0000002943 | NEW | no |  | 0 | 0.9 |  | - | AllplanAttributes - ash D_Detailverweis: <undefiniert>; Sicherheitsklasse: -; Sonnenschutztyp: Movable; g-Wert: 0,51
 | H2 Ebene +2 | WA-DL | 1205Wa 0000002967 | yes |  | m³ | Zimmer- und Holzbauarbeiten | Wand | Außenwand 2-Schalig | WA-DL |  |  | 7.5 | 1205HWa0000002943 | NEW | no |  | 0 | 0.9 |  | - | AllplanAttributes - ash D_Detailverweis: <undefiniert>; Sicherheitsklasse: -; Sonnenschutztyp: Movable; g-Wert: 0,51
 | H2 Ebene +2 | WA-LB | 1205Wa 0000002971 | yes | Codetext | m² | Trockenbauarbeiten | Wand | Außenwand 2-Schalig | WA-LB | 0 | A | 7.5 | 1205HWa0000002943 | NEW | no | yes | 0 | 0.9 | no | - | no | Codetext | AllplanAttributes - ash D_Detailverweis: <undefiniert>; Sicherheitsklasse: -; Sonnenschutztyp: Movable; g-Wert: 0,51
 | H2 Ebene +2 | WA-TL | 1205Wa 0000002975 | yes |  | m² | Zimmer- und Holzbauarbeiten | Wand | Außenwand 2-Schalig | WA-TL |  |  | 7.5 | 1205HWa0000002943 | NEW | no |  | 0 | 0.9 |  | - | AllplanAttributes - ash D_Detailverweis: <undefiniert>; Sicherheitsklasse: -; Sonnenschutztyp: Movable; g-Wert: 0,51
Traglattung | H2 Ebene +2 | WA-TL | 1205Wa 0000002979 | yes |  | m² | Zimmer- und Holzbauarbeiten | Wand | Traglattung | WA-TL |  |  | 7.5 | 1205HWa0000002943 | NEW | no | yes | 0 | 0.9 |  | - | AllplanAttributes - ash D_Detailverweis: <undefiniert>; Sicherheitsklasse: -; Sonnenschutztyp: Movable; g-Wert: 0,51
 | H2 Ebene +2 | WA-HS | 1205Wa 0000091817 | yes |  | m² | Zimmer- und Holzbauarbeiten | Wand | Außenwand 2-Schalig | WA-HS |  |  | 7.5 | 1205HWa0000002943 | NEW | no |  | 0 | 0.9 |  | - | AllplanAttributes - ash D_Detailverweis: <undefiniert>; Sicherheitsklasse: -; Sonnenschutztyp: Movable; g-Wert: 0,51
 | H2 Ebene +2 | WA-STB | 1205Wa 0000002989 | yes | Codetext | m² | Zimmer- und Holzbauarbeiten | Wand | Außenwand 2-Schalig | WA-STB | 0 | A | 7.5 | 1205HWa0000002929 | NEW | no | yes | 0 | 0.9 | no | 32 | no | Codetext | AllplanAttributes - ash D_Detailverweis: <undefiniert>; Sicherheitsklasse: -; Sonnenschutztyp: Movable; g-Wert: 0,51
 | H2 Ebene +2 | WA-DL | 1205Wa 0000002987 | yes | Codetext | m³ | Zimmer- und Holzbauarbeiten | Wand | Außenwand 2-Schalig | WA-DL | 0 | A | 7.5 | 1205HWa0000002929 | NEW | no | yes | 0 | 0.9 | no | 32 | no | Codetext | AllplanAttributes - ash D_Detailverweis: <undefiniert>; Sicherheitsklasse: -; Sonnenschutztyp: Movable; g-Wert: 0,51
 | H2 Ebene +2 | WA-LB | 1205Wa 0000002985 | yes | Codetext | m² | Trockenbauarbeiten | Wand | Außenwand 2-Schalig | WA-LB | 0 | A | 7.5 | 1205HWa0000002929 | NEW | no | yes | 0 | 0.9 | no | 32 | no | Codetext | AllplanAttributes - ash D_Detailverweis: <undefiniert>; Sicherheitsklasse: -; Sonnenschutztyp: Movable; g-Wert: 0,51
 | H2 Ebene +2 | WA-KL | 1205Wa 0000002983 | yes | Codetext | m² | Zimmer- und Holzbauarbeiten | Wand | Außenwand 2-Schalig | WA-KL | 0 | A | 7.5 | 1205HWa0000002929 | NEW | no | yes | 0 | 0.9 | no | 32 | no | Codetext | AllplanAttributes - ash D_Detailverweis: <undefiniert>; Sicherheitsklasse: -; Sonnenschutztyp: Movable; g-Wert: 0,51
 | H2 Ebene +2 | WA-TL | 1205Wa 0000002981 | yes | Codetext | m² | Zimmer- und Holzbauarbeiten | Wand | Außenwand 2-Schalig | WA-TL | 0 | A | 7.5 | 1205HWa0000002929 | NEW | no | yes | 0 | 0.9 | no | 32 | no | Codetext | AllplanAttributes - ash D_Detailverweis: <undefiniert>; Sicherheitsklasse: -; Sonnenschutztyp: Movable; g-Wert: 0,51
 | H2 Ebene +2 | WA-HS | 1205Wa 0000092314 | yes | Codetext | m² | Zimmer- und Holzbauarbeiten | Wand | Außenwand 2-Schalig | WA-HS | 0 | A | 7.5 | 1205HWa0000002929 | NEW | no | yes | 0 | 0.9 | no | 32 | no | Codetext | AllplanAttributes - ash D_Detailverweis: <undefiniert>; Sicherheitsklasse: -; Sonnenschutztyp: Movable; g-Wert: 0,51
 | H2 Ebene +2 | WA-STB | 1205Wa 0000003026 | yes | Codetext | m² | Zimmer- und Holzbauarbeiten | Wand | Außenwand 2-Schalig | WA-STB | 0 | A | 7.5 | 1205HWa0000002941 | NEW | no | yes | 0 | 0.9 | no | 32 | no | Codetext | AllplanAttributes - ash D_Detailverweis: <undefiniert>; Sicherheitsklasse: -; Sonnenschutztyp: Movable; g-Wert: 0,51
 | H2 Ebene +2 | WA-DL | 1205Wa 0000003024 | yes | Codetext | m³ | Zimmer- und Holzbauarbeiten | Wand | Außenwand 2-Schalig | WA-DL | 0 | A | 7.5 | 1205HWa0000002941 | NEW | no | yes | 0 | 0.9 | no | 32 | no | Codetext | AllplanAttributes - ash D_Detailverweis: <undefiniert>; Sicherheitsklasse: -; Sonnenschutztyp: Movable; g-Wert: 0,51
 | H2 Ebene +2 | WA-LB | 1205Wa 0000003022 | yes | Codetext | m² | Trockenbauarbeiten | Wand | Außenwand 2-Schalig | WA-LB | 0 | A | 7.5 | 1205HWa0000002941 | NEW | no | yes | 0 | 0.9 | no | 32 | no | Codetext | AllplanAttributes - ash D_Detailverweis: <undefiniert>; Sicherheitsklasse: -; Sonnenschutztyp: Movable; g-Wert: 0,51
 | H2 Ebene +2 | WA-KL | 1205Wa 0000003020 | yes | Codetext | m² | Zimmer- und Holzbauarbeiten | Wand | Außenwand 2-Schalig | WA-KL | 0 | A | 7.5 | 1205HWa0000002941 | NEW | no | yes | 0 | 0.9 | no | 32 | no | Codetext | AllplanAttributes - ash D_Detailverweis: <undefiniert>; Sicherheitsklasse: -; Sonnenschutztyp: Movable; g-Wert: 0,51
 | H2 Ebene +2 | WA-TL | 1205Wa 0000003018 | yes | Codetext | m² | Zimmer- und Holzbauarbeiten | Wand | Außenwand 2-Schalig | WA-TL | 0 | A | 7.5 | 1205HWa0000002941 | NEW | no | yes | 0 | 0.9 | no | 32 | no | Codetext | AllplanAttributes - ash D_Detailverweis: <undefiniert>; Sicherheitsklasse: -; Sonnenschutztyp: Movable; g-Wert: 0,51
 | H2 Ebene +2 | WA-HS | 1205Wa 0000092209 | yes | Codetext | m² | Zimmer- und Holzbauarbeiten | Wand | Außenwand 2-Schalig | WA-HS | 0 | A | 7.5 | 1205HWa0000002941 | NEW | no | yes | 0 | 0.9 | no | 32 | no | Codetext | AllplanAttributes - ash D_Detailverweis: <undefiniert>; Sicherheitsklasse: -; Sonnenschutztyp: Movable; g-Wert: 0,51
 | H2 Ebene +2 | WA-STB | 1205Wa 0000100570 | yes |  | m² | Zimmer- und Holzbauarbeiten | Wand | Außenwand 2-Schalig | WA-STB |  |  | 7.5 | 1205HWa0000100569 | NEW | no |  | 0 | 0.9 |  | 32 | AllplanAttributes - ash D_Detailverweis: <undefiniert>; Sicherheitsklasse: -; Sonnenschutztyp: Movable; g-Wert: 0,51
 | H2 Ebene +2 | WA-DL | 1205Wa 0000100571 | yes |  | m³ | Zimmer- und Holzbauarbeiten | Wand | Außenwand 2-Schalig | WA-DL |  |  | 7.5 | 1205HWa0000100569 | NEW | no |  | 0 | 0.9 |  | 32 | AllplanAttributes - ash D_Detailverweis: <undefiniert>; Sicherheitsklasse: -; Sonnenschutztyp: Movable; g-Wert: 0,51
 | H2 Ebene +2 | WA-LB | 1205Wa 0000100572 | yes | Codetext | m² | Trockenbauarbeiten | Wand | Außenwand 2-Schalig | WA-LB | 0 | A | 7.5 | 1205HWa0000100569 | NEW | no | yes | 0 | 0.9 | no | 32 | no | Codetext | AllplanAttributes - ash D_Detailverweis: <undefiniert>; Sicherheitsklasse: -; Sonnenschutztyp: Movable; g-Wert: 0,51
 | H2 Ebene +2 | WA-TL | 1205Wa 0000100573 | yes |  | m² | Zimmer- und Holzbauarbeiten | Wand | Außenwand 2-Schalig | WA-TL |  |  | 7.5 | 1205HWa0000100569 | NEW | no |  | 0 | 0.9 |  | 32 | AllplanAttributes - ash D_Detailverweis: <undefiniert>; Sicherheitsklasse: -; Sonnenschutztyp: Movable; g-Wert: 0,51
Traglattung | H2 Ebene +2 | WA-TL | 1205Wa 0000100574 | yes |  | m² | Zimmer- und Holzbauarbeiten | Wand | Traglattung | WA-TL |  |  | 7.5 | 1205HWa0000100569 | NEW | no | yes | 0 | 0.9 |  | 32 | AllplanAttributes - ash D_Detailverweis: <undefiniert>; Sicherheitsklasse: -; Sonnenschutztyp: Movable; g-Wert: 0,51
 | H2 Ebene +2 | WA-HS | 1205Wa 0000100575 | yes |  | m² | Zimmer- und Holzbauarbeiten | Wand | Außenwand 2-Schalig | WA-HS |  |  | 7.5 | 1205HWa0000100569 | NEW | no |  | 0 | 0.9 |  | 32 | AllplanAttributes - ash D_Detailverweis: <undefiniert>; Sicherheitsklasse: -; Sonnenschutztyp: Movable; g-Wert: 0,51
 | H2 Ebene +2 | WA-STB | 1205Wa 0000100636 | yes |  | m² | Zimmer- und Holzbauarbeiten | Wand | Außenwand 2-Schalig | WA-STB |  |  | 7.5 | 1205HWa0000100635 | NEW | no |  | 0 | 0.9 |  | 32 | AllplanAttributes - ash D_Detailverweis: <undefiniert>; Sicherheitsklasse: -; Sonnenschutztyp: Movable; g-Wert: 0,51
 | H2 Ebene +2 | WA-DL | 1205Wa 0000100637 | yes |  | m³ | Zimmer- und Holzbauarbeiten | Wand | Außenwand 2-Schalig | WA-DL |  |  | 7.5 | 1205HWa0000100635 | NEW | no |  | 0 | 0.9 |  | 32 | AllplanAttributes - ash D_Detailverweis: <undefiniert>; Sicherheitsklasse: -; Sonnenschutztyp: Movable; g-Wert: 0,51
 | H2 Ebene +2 | WA-LB | 1205Wa 0000100638 | yes | Codetext | m² | Trockenbauarbeiten | Wand | Außenwand 2-Schalig | WA-LB | 0 | A | 7.5 | 1205HWa0000100635 | NEW | no | yes | 0 | 0.9 | no | 32 | no | Codetext | AllplanAttributes - ash D_Detailverweis: <undefiniert>; Sicherheitsklasse: -; Sonnenschutztyp: Movable; g-Wert: 0,51
 | H2 Ebene +2 | WA-TL | 1205Wa 0000100639 | yes |  | m² | Zimmer- und Holzbauarbeiten | Wand | Außenwand 2-Schalig | WA-TL |  |  | 7.5 | 1205HWa0000100635 | NEW | no |  | 0 | 0.9 |  | 32 | AllplanAttributes - ash D_Detailverweis: <undefiniert>; Sicherheitsklasse: -; Sonnenschutztyp: Movable; g-Wert: 0,51
Traglattung | H2 Ebene +2 | WA-TL | 1205Wa 0000100640 | yes |  | m² | Zimmer- und Holzbauarbeiten | Wand | Traglattung | WA-TL |  |  | 7.5 | 1205HWa0000100635 | NEW | no | yes | 0 | 0.9 |  | 32 | AllplanAttributes - ash D_Detailverweis: <undefiniert>; Sicherheitsklasse: -; Sonnenschutztyp: Movable; g-Wert: 0,51
 | H2 Ebene +2 | WA-HS | 1205Wa 0000100641 | yes |  | m² | Zimmer- und Holzbauarbeiten | Wand | Außenwand 2-Schalig | WA-HS |  |  | 7.5 | 1205HWa0000100635 | NEW | no |  | 0 | 0.9 |  | 32 | AllplanAttributes - ash D_Detailverweis: <undefiniert>; Sicherheitsklasse: -; Sonnenschutztyp: Movable; g-Wert: 0,51
 | H2 Ebene +2 | WA-LB | 1205Wa 0000101990 | yes | Codetext | m² | Trockenbauarbeiten | Wand | Außenwand 7-Schalig | WA-LB | 0 | A | 7.5 | 1205HWa0000101952 | NEW | no | yes | 0 | 0.9 | no | 32 | no | Codetext | AllplanAttributes - ash D_Detailverweis: <undefiniert>; Sicherheitsklasse: -; Sonnenschutztyp: Movable; g-Wert: 0,51
 | H2 Ebene +2 | WA-HD | 1205Wa 0000102005 | yes | Codetext | m³ | Zimmer- und Holzbauarbeiten | Wand | Außenwand 7-Schalig | WA-HD | 0 | A | 7.5 | 1205HWa0000101952 | NEW | no | yes | 0 | 0.9 | no | 32 | no | Codetext | AllplanAttributes - ash D_Detailverweis: <undefiniert>; Sicherheitsklasse: -; Sonnenschutztyp: Movable; g-Wert: 0,51; ash W_laufende Nr. Statik: 2 (W 2.0/ 2.1/ 2.2)
 | H2 Ebene +2 | WA-DL | 1205Wa 0000102020 | yes | Codetext | m³ | Zimmer- und Holzbauarbeiten | Wand | Außenwand 7-Schalig | WA-DL | 0 | A | 7.5 | 1205HWa0000101952 | NEW | no | yes | 0 | 0.9 | no | 32 | no | Codetext | AllplanAttributes - ash D_Detailverweis: <undefiniert>; Sicherheitsklasse: -; Sonnenschutztyp: Movable; g-Wert: 0,51
 | H2 Ebene +2 | WA-LB | 1205Wa 0000102017 | yes | Codetext | m² | Trockenbauarbeiten | Wand | Außenwand 7-Schalig | WA-LB | 0 | A | 7.5 | 1205HWa0000101952 | NEW | no | yes | 0 | 0.9 | no | 32 | no | Codetext | AllplanAttributes - ash D_Detailverweis: <undefiniert>; Sicherheitsklasse: -; Sonnenschutztyp: Movable; g-Wert: 0,51
 | H2 Ebene +2 | WA-KL | 1205Wa 0000102014 | yes | Codetext | m² | Zimmer- und Holzbauarbeiten | Wand | Außenwand 7-Schalig | WA-KL | 0 | A | 7.5 | 1205HWa0000101952 | NEW | no | yes | 0 | 0.9 | no | 32 | no | Codetext | AllplanAttributes - ash D_Detailverweis: <undefiniert>; Sicherheitsklasse: -; Sonnenschutztyp: Movable; g-Wert: 0,51
 | H2 Ebene +2 | WA-TL | 1205Wa 0000102011 | yes | Codetext | m² | Zimmer- und Holzbauarbeiten | Wand | Außenwand 7-Schalig | WA-TL | 0 | A | 7.5 | 1205HWa0000101952 | NEW | no | yes | 0 | 0.9 | no | 32 | no | Codetext | AllplanAttributes - ash D_Detailverweis: <undefiniert>; Sicherheitsklasse: -; Sonnenschutztyp: Movable; g-Wert: 0,51
 | H2 Ebene +2 | WA-HS | 1205Wa 0000102008 | yes | Codetext | m² | Zimmer- und Holzbauarbeiten | Wand | Außenwand 7-Schalig | WA-HS | 0 | A | 7.5 | 1205HWa0000101952 | NEW | no | yes | 0 | 0.9 | no | 32 | no | Codetext | AllplanAttributes - ash D_Detailverweis: <undefiniert>; Sicherheitsklasse: -; Sonnenschutztyp: Movable; g-Wert: 0,51
 | H2 Ebene +2 | WA-LB | 1205Wa 0000102162 | yes | Codetext | m² | Trockenbauarbeiten | Wand | Außenwand 7-Schalig | WA-LB | 0 | A | 7.5 | 1205HWa0000102132 | NEW | no | yes | 0 | 0.9 | no | 32 | no | Codetext | AllplanAttributes - ash D_Detailverweis: <undefiniert>; Sicherheitsklasse: -; Sonnenschutztyp: Movable; g-Wert: 0,51
 | H2 Ebene +2 | WA-HD | 1205Wa 0000102160 | yes | Codetext | m³ | Zimmer- und Holzbauarbeiten | Wand | Außenwand 7-Schalig | WA-HD | 0 | A | 7.5 | 1205HWa0000102132 | NEW | no | yes | 0 | 0.9 | no | 32 | no | Codetext | AllplanAttributes - ash D_Detailverweis: <undefiniert>; Sicherheitsklasse: -; Sonnenschutztyp: Movable; g-Wert: 0,51; ash W_laufende Nr. Statik: 2 (W 2.0/ 2.1/ 2.2)
 | H2 Ebene +2 | WA-DL | 1205Wa 0000102158 | yes | Codetext | m³ | Zimmer- und Holzbauarbeiten | Wand | Außenwand 7-Schalig | WA-DL | 0 | A | 7.5 | 1205HWa0000102132 | NEW | no | yes | 0 | 0.9 | no | 32 | no | Codetext | AllplanAttributes - ash D_Detailverweis: <undefiniert>; Sicherheitsklasse: -; Sonnenschutztyp: Movable; g-Wert: 0,51
 | H2 Ebene +2 | WA-LB | 1205Wa 0000102156 | yes | Codetext | m² | Trockenbauarbeiten | Wand | Außenwand 7-Schalig | WA-LB | 0 | A | 7.5 | 1205HWa0000102132 | NEW | no | yes | 0 | 0.9 | no | 32 | no | Codetext | AllplanAttributes - ash D_Detailverweis: <undefiniert>; Sicherheitsklasse: -; Sonnenschutztyp: Movable; g-Wert: 0,51
 | H2 Ebene +2 | WA-KL | 1205Wa 0000102154 | yes | Codetext | m² | Zimmer- und Holzbauarbeiten | Wand | Außenwand 7-Schalig | WA-KL | 0 | A | 7.5 | 1205HWa0000102132 | NEW | no | yes | 0 | 0.9 | no | 32 | no | Codetext | AllplanAttributes - ash D_Detailverweis: <undefiniert>; Sicherheitsklasse: -; Sonnenschutztyp: Movable; g-Wert: 0,51
 | H2 Ebene +2 | WA-TL | 1205Wa 0000102152 | yes | Codetext | m² | Zimmer- und Holzbauarbeiten | Wand | Außenwand 7-Schalig | WA-TL | 0 | A | 7.5 | 1205HWa0000102132 | NEW | no | yes | 0 | 0.9 | no | 32 | no | Codetext | AllplanAttributes - ash D_Detailverweis: <undefiniert>; Sicherheitsklasse: -; Sonnenschutztyp: Movable; g-Wert: 0,51
 | H2 Ebene +2 | WA-HS | 1205Wa 0000102150 | yes | Codetext | m² | Zimmer- und Holzbauarbeiten | Wand | Außenwand 7-Schalig | WA-HS | 0 | A | 7.5 | 1205HWa0000102132 | NEW | no | yes | 0 | 0.9 | no | 32 | no | Codetext | AllplanAttributes - ash D_Detailverweis: <undefiniert>; Sicherheitsklasse: -; Sonnenschutztyp: Movable; g-Wert: 0,51
 | H2 Ebene +2 | WA-LB | 1205Wa 0000102148 | yes | Codetext | m² | Trockenbauarbeiten | Wand | Außenwand 7-Schalig | WA-LB | 0 | A | 7.5 | 1205HWa0000102131 | NEW | no | yes | 0 | 0.9 | no | 32 | no | Codetext | AllplanAttributes - ash D_Detailverweis: <undefiniert>; Sicherheitsklasse: -; Sonnenschutztyp: Movable; g-Wert: 0,51
 | H2 Ebene +2 | WA-HD | 1205Wa 0000102146 | yes | Codetext | m³ | Zimmer- und Holzbauarbeiten | Wand | Außenwand 7-Schalig | WA-HD | 0 | A | 7.5 | 1205HWa0000102131 | NEW | no | yes | 0 | 0.9 | no | 32 | no | Codetext | AllplanAttributes - ash D_Detailverweis: <undefiniert>; Sicherheitsklasse: -; Sonnenschutztyp: Movable; g-Wert: 0,51; ash W_laufende Nr. Statik: 2 (W 2.0/ 2.1/ 2.2)
 | H2 Ebene +2 | WA-DL | 1205Wa 0000102144 | yes | Codetext | m³ | Zimmer- und Holzbauarbeiten | Wand | Außenwand 7-Schalig | WA-DL | 0 | A | 7.5 | 1205HWa0000102131 | NEW | no | yes | 0 | 0.9 | no | 32 | no | Codetext | AllplanAttributes - ash D_Detailverweis: <undefiniert>; Sicherheitsklasse: -; Sonnenschutztyp: Movable; g-Wert: 0,51
 | H2 Ebene +2 | WA-LB | 1205Wa 0000102142 | yes | Codetext | m² | Trockenbauarbeiten | Wand | Außenwand 7-Schalig | WA-LB | 0 | A | 7.5 | 1205HWa0000102131 | NEW | no | yes | 0 | 0.9 | no | 32 | no | Codetext | AllplanAttributes - ash D_Detailverweis: <undefiniert>; Sicherheitsklasse: -; Sonnenschutztyp: Movable; g-Wert: 0,51
 | H2 Ebene +2 | WA-KL | 1205Wa 0000102140 | yes | Codetext | m² | Zimmer- und Holzbauarbeiten | Wand | Außenwand 7-Schalig | WA-KL | 0 | A | 7.5 | 1205HWa0000102131 | NEW | no | yes | 0 | 0.9 | no | 32 | no | Codetext | AllplanAttributes - ash D_Detailverweis: <undefiniert>; Sicherheitsklasse: -; Sonnenschutztyp: Movable; g-Wert: 0,51
 | H2 Ebene +2 | WA-TL | 1205Wa 0000102138 | yes | Codetext | m² | Zimmer- und Holzbauarbeiten | Wand | Außenwand 7-Schalig | WA-TL | 0 | A | 7.5 | 1205HWa0000102131 | NEW | no | yes | 0 | 0.9 | no | 32 | no | Codetext | AllplanAttributes - ash D_Detailverweis: <undefiniert>; Sicherheitsklasse: -; Sonnenschutztyp: Movable; g-Wert: 0,51
 | H2 Ebene +2 | WA-HS | 1205Wa 0000102136 | yes | Codetext | m² | Zimmer- und Holzbauarbeiten | Wand | Außenwand 7-Schalig | WA-HS | 0 | A | 7.5 | 1205HWa0000102131 | NEW | no | yes | 0 | 0.9 | no | 32 | no | Codetext | AllplanAttributes - ash D_Detailverweis: <undefiniert>; Sicherheitsklasse: -; Sonnenschutztyp: Movable; g-Wert: 0,51
 | H2 Ebene +2 | WA-STB | 1205Wa 0000102324 | yes | Codetext | m² | Zimmer- und Holzbauarbeiten | Wand | Außenwand 2-Schalig | WA-STB | 0 | A | 7.5 | 1205HWa0000101939 | NEW | no | yes | 0 | 0.9 | no | 32 | no | Codetext | AllplanAttributes - ash D_Detailverweis: <undefiniert>; Sicherheitsklasse: -; Sonnenschutztyp: Movable; g-Wert: 0,51
 | H2 Ebene +2 | WA-DL | 1205Wa 0000102272 | yes | Codetext | m³ | Zimmer- und Holzbauarbeiten | Wand | Außenwand 2-Schalig | WA-DL | 0 | A | 7.5 | 1205HWa0000101939 | NEW | no | yes | 0 | 0.9 | no | 32 | no | Codetext | AllplanAttributes - ash D_Detailverweis: <undefiniert>; Sicherheitsklasse: -; Sonnenschutztyp: Movable; g-Wert: 0,51
 | H2 Ebene +2 | WA-LB | 1205Wa 0000102269 | yes | Codetext | m² | Trockenbauarbeiten | Wand | Außenwand 2-Schalig | WA-LB | 0 | A | 7.5 | 1205HWa0000101939 | NEW | no | yes | 0 | 0.9 | no | 32 | no | Codetext | AllplanAttributes - ash D_Detailverweis: <undefiniert>; Sicherheitsklasse: -; Sonnenschutztyp: Movable; g-Wert: 0,51
 | H2 Ebene +2 | WA-KL | 1205Wa 0000102267 | yes | Codetext | m² | Zimmer- und Holzbauarbeiten | Wand | Außenwand 2-Schalig | WA-KL | 0 | A | 7.5 | 1205HWa0000101939 | NEW | no | yes | 0 | 0.9 | no | 32 | no | Codetext | AllplanAttributes - ash D_Detailverweis: <undefiniert>; Sicherheitsklasse: -; Sonnenschutztyp: Movable; g-Wert: 0,51
 | H2 Ebene +2 | WA-TL | 1205Wa 0000102265 | yes | Codetext | m² | Zimmer- und Holzbauarbeiten | Wand | Außenwand 2-Schalig | WA-TL | 0 | A | 7.5 | 1205HWa0000101939 | NEW | no | yes | 0 | 0.9 | no | 32 | no | Codetext | AllplanAttributes - ash D_Detailverweis: <undefiniert>; Sicherheitsklasse: -; Sonnenschutztyp: Movable; g-Wert: 0,51
 | H2 Ebene +2 | WA-HS | 1205Wa 0000102263 | yes | Codetext | m² | Zimmer- und Holzbauarbeiten | Wand | Außenwand 2-Schalig | WA-HS | 0 | A | 7.5 | 1205HWa0000101939 | NEW | no | yes | 0 | 0.9 | no | 32 | no | Codetext | AllplanAttributes - ash D_Detailverweis: <undefiniert>; Sicherheitsklasse: -; Sonnenschutztyp: Movable; g-Wert: 0,51
 | H2 Ebene +2 | WA-LB | 1205Wa 0000102069 | yes | Codetext | m² | Trockenbauarbeiten | Wand | Außenwand 7-Schalig | WA-LB | 0 | A | 7.5 | 1205HWa0000102029 | NEW | no | yes | 0 | 0.9 | no | 32 | no | Codetext | AllplanAttributes - ash D_Detailverweis: <undefiniert>; Sicherheitsklasse: -; Sonnenschutztyp: Movable; g-Wert: 0,51
 | H2 Ebene +2 | WA-HD | 1205Wa 0000102066 | yes | Codetext | m³ | Zimmer- und Holzbauarbeiten | Wand | Außenwand 7-Schalig | WA-HD | 0 | A | 7.5 | 1205HWa0000102029 | NEW | no | yes | 0 | 0.9 | no | 32 | no | Codetext | AllplanAttributes - ash D_Detailverweis: <undefiniert>; Sicherheitsklasse: -; Sonnenschutztyp: Movable; g-Wert: 0,51; ash W_laufende Nr. Statik: 2 (W 2.0/ 2.1/ 2.2)
 | H2 Ebene +2 | WA-DL | 1205Wa 0000102063 | yes | Codetext | m³ | Zimmer- und Holzbauarbeiten | Wand | Außenwand 7-Schalig | WA-DL | 0 | A | 7.5 | 1205HWa0000102029 | NEW | no | yes | 0 | 0.9 | no | 32 | no | Codetext | AllplanAttributes - ash D_Detailverweis: <undefiniert>; Sicherheitsklasse: -; Sonnenschutztyp: Movable; g-Wert: 0,51
 | H2 Ebene +2 | WA-LB | 1205Wa 0000102060 | yes | Codetext | m² | Trockenbauarbeiten | Wand | Außenwand 7-Schalig | WA-LB | 0 | A | 7.5 | 1205HWa0000102029 | NEW | no | yes | 0 | 0.9 | no | 32 | no | Codetext | AllplanAttributes - ash D_Detailverweis: <undefiniert>; Sicherheitsklasse: -; Sonnenschutztyp: Movable; g-Wert: 0,51
 | H2 Ebene +2 | WA-KL | 1205Wa 0000102057 | yes | Codetext | m² | Zimmer- und Holzbauarbeiten | Wand | Außenwand 7-Schalig | WA-KL | 0 | A | 7.5 | 1205HWa0000102029 | NEW | no | yes | 0 | 0.9 | no | 32 | no | Codetext | AllplanAttributes - ash D_Detailverweis: <undefiniert>; Sicherheitsklasse: -; Sonnenschutztyp: Movable; g-Wert: 0,51
 | H2 Ebene +2 | WA-TL | 1205Wa 0000102054 | yes | Codetext | m² | Zimmer- und Holzbauarbeiten | Wand | Außenwand 7-Schalig | WA-TL | 0 | A | 7.5 | 1205HWa0000102029 | NEW | no | yes | 0 | 0.9 | no | 32 | no | Codetext | AllplanAttributes - ash D_Detailverweis: <undefiniert>; Sicherheitsklasse: -; Sonnenschutztyp: Movable; g-Wert: 0,51
 | H2 Ebene +2 | WA-HS | 1205Wa 0000102051 | yes | Codetext | m² | Zimmer- und Holzbauarbeiten | Wand | Außenwand 7-Schalig | WA-HS | 0 | A | 7.5 | 1205HWa0000102029 | NEW | no | yes | 0 | 0.9 | no | 32 | no | Codetext | AllplanAttributes - ash D_Detailverweis: <undefiniert>; Sicherheitsklasse: -; Sonnenschutztyp: Movable; g-Wert: 0,51
 | H2 Ebene +2 | WA-LB | 1205Wa 0000102083 | yes | Codetext | m² | Trockenbauarbeiten | Wand | Außenwand 7-Schalig | WA-LB | 0 | A | 7.5 | 1205HWa0000101946 | NEW | no | yes | 0 | 0.9 | no | 32 | no | Codetext | AllplanAttributes - ash D_Detailverweis: <undefiniert>; Sicherheitsklasse: -; Sonnenschutztyp: Movable; g-Wert: 0,51
 | H2 Ebene +2 | WA-HD | 1205Wa 0000102081 | yes | Codetext | m³ | Zimmer- und Holzbauarbeiten | Wand | Außenwand 7-Schalig | WA-HD | 0 | A | 7.5 | 1205HWa0000101946 | NEW | no | yes | 0 | 0.9 | no | 32 | no | Codetext | AllplanAttributes - ash D_Detailverweis: <undefiniert>; Sicherheitsklasse: -; Sonnenschutztyp: Movable; g-Wert: 0,51; ash W_laufende Nr. Statik: 2 (W 2.0/ 2.1/ 2.2)
 | H2 Ebene +2 | WA-DL | 1205Wa 0000102079 | yes | Codetext | m³ | Zimmer- und Holzbauarbeiten | Wand | Außenwand 7-Schalig | WA-DL | 0 | A | 7.5 | 1205HWa0000101946 | NEW | no | yes | 0 | 0.9 | no | 32 | no | Codetext | AllplanAttributes - ash D_Detailverweis: <undefiniert>; Sicherheitsklasse: -; Sonnenschutztyp: Movable; g-Wert: 0,51
 | H2 Ebene +2 | WA-LB | 1205Wa 0000102077 | yes | Codetext | m² | Trockenbauarbeiten | Wand | Außenwand 7-Schalig | WA-LB | 0 | A | 7.5 | 1205HWa0000101946 | NEW | no | yes | 0 | 0.9 | no | 32 | no | Codetext | AllplanAttributes - ash D_Detailverweis: <undefiniert>; Sicherheitsklasse: -; Sonnenschutztyp: Movable; g-Wert: 0,51
 | H2 Ebene +2 | WA-KL | 1205Wa 0000102075 | yes | Codetext | m² | Zimmer- und Holzbauarbeiten | Wand | Außenwand 7-Schalig | WA-KL | 0 | A | 7.5 | 1205HWa0000101946 | NEW | no | yes | 0 | 0.9 | no | 32 | no | Codetext | AllplanAttributes - ash D_Detailverweis: <undefiniert>; Sicherheitsklasse: -; Sonnenschutztyp: Movable; g-Wert: 0,51
 | H2 Ebene +2 | WA-TL | 1205Wa 0000102073 | yes | Codetext | m² | Zimmer- und Holzbauarbeiten | Wand | Außenwand 7-Schalig | WA-TL | 0 | A | 7.5 | 1205HWa0000101946 | NEW | no | yes | 0 | 0.9 | no | 32 | no | Codetext | AllplanAttributes - ash D_Detailverweis: <undefiniert>; Sicherheitsklasse: -; Sonnenschutztyp: Movable; g-Wert: 0,51
 | H2 Ebene +2 | WA-HS | 1205Wa 0000102071 | yes | Codetext | m² | Zimmer- und Holzbauarbeiten | Wand | Außenwand 7-Schalig | WA-HS | 0 | A | 7.5 | 1205HWa0000101946 | NEW | no | yes | 0 | 0.9 | no | 32 | no | Codetext | AllplanAttributes - ash D_Detailverweis: <undefiniert>; Sicherheitsklasse: -; Sonnenschutztyp: Movable; g-Wert: 0,51
 | H2 Ebene +2 | WA-LB | 1205Wa 0000101987 | yes | Codetext | m² | Trockenbauarbeiten | Wand | Außenwand 7-Schalig | WA-LB | 0 | A | 7.5 | 1205HWa0000101948 | NEW | no | yes | 0 | 0.9 | no | 32 | no | Codetext | AllplanAttributes - ash D_Detailverweis: <undefiniert>; Sicherheitsklasse: -; Sonnenschutztyp: Movable; g-Wert: 0,51
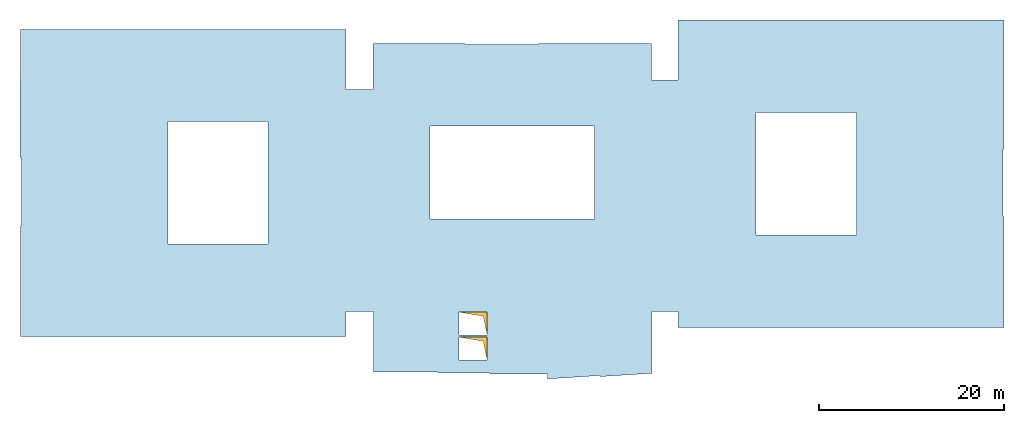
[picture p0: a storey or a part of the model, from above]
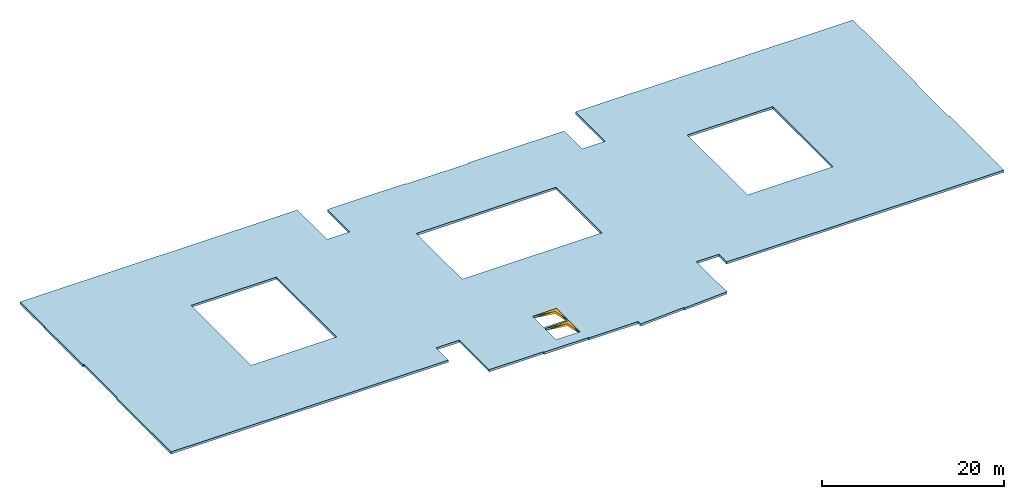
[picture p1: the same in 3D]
Properties of the parts of a building model (IFC4), part 51 of 80

# IfcWall (6826)
Name | In | Material | Allright_Bauteil_ID | 2D Interaktion | Codetext | Abrechnungsart | Gewerk | Objektname | Bezeichnung | AllplanAttributes, Material | Typ = SurfaceSpreadOfFlame | Brandschutzklasse | OKFF | P_ID | Status | LoadBearing | IsExternal | FireRating | ThermalTransmittance (W/K/m2) | Combustible | AcousticRating | Compartmentation | Reference
 | H2 Ebene +2 | WA-HD | 1205Wa 0000101985 | yes | Codetext | m³ | Zimmer- und Holzbauarbeiten | Wand | Außenwand 7-Schalig | WA-HD | 0 | A | 7.5 | 1205HWa0000101948 | NEW | no | yes | 0 | 0.9 | no | 32 | no | Codetext | AllplanAttributes - ash D_Detailverweis: <undefiniert>; Sicherheitsklasse: -; Sonnenschutztyp: Movable; g-Wert: 0,51; ash W_laufende Nr. Statik: 2 (W 2.0/ 2.1/ 2.2)
 | H2 Ebene +2 | WA-DL | 1205Wa 0000101983 | yes | Codetext | m³ | Zimmer- und Holzbauarbeiten | Wand | Außenwand 7-Schalig | WA-DL | 0 | A | 7.5 | 1205HWa0000101948 | NEW | no | yes | 0 | 0.9 | no | 32 | no | Codetext | AllplanAttributes - ash D_Detailverweis: <undefiniert>; Sicherheitsklasse: -; Sonnenschutztyp: Movable; g-Wert: 0,51
 | H2 Ebene +2 | WA-LB | 1205Wa 0000101981 | yes | Codetext | m² | Trockenbauarbeiten | Wand | Außenwand 7-Schalig | WA-LB | 0 | A | 7.5 | 1205HWa0000101948 | NEW | no | yes | 0 | 0.9 | no | 32 | no | Codetext | AllplanAttributes - ash D_Detailverweis: <undefiniert>; Sicherheitsklasse: -; Sonnenschutztyp: Movable; g-Wert: 0,51
 | H2 Ebene +2 | WA-KL | 1205Wa 0000101979 | yes | Codetext | m² | Zimmer- und Holzbauarbeiten | Wand | Außenwand 7-Schalig | WA-KL | 0 | A | 7.5 | 1205HWa0000101948 | NEW | no | yes | 0 | 0.9 | no | 32 | no | Codetext | AllplanAttributes - ash D_Detailverweis: <undefiniert>; Sicherheitsklasse: -; Sonnenschutztyp: Movable; g-Wert: 0,51
 | H2 Ebene +2 | WA-TL | 1205Wa 0000101977 | yes | Codetext | m² | Zimmer- und Holzbauarbeiten | Wand | Außenwand 7-Schalig | WA-TL | 0 | A | 7.5 | 1205HWa0000101948 | NEW | no | yes | 0 | 0.9 | no | 32 | no | Codetext | AllplanAttributes - ash D_Detailverweis: <undefiniert>; Sicherheitsklasse: -; Sonnenschutztyp: Movable; g-Wert: 0,51
 | H2 Ebene +2 | WA-HS | 1205Wa 0000101975 | yes | Codetext | m² | Zimmer- und Holzbauarbeiten | Wand | Außenwand 7-Schalig | WA-HS | 0 | A | 7.5 | 1205HWa0000101948 | NEW | no | yes | 0 | 0.9 | no | 32 | no | Codetext | AllplanAttributes - ash D_Detailverweis: <undefiniert>; Sicherheitsklasse: -; Sonnenschutztyp: Movable; g-Wert: 0,51
 | H2 Ebene +2 | WA-STB | 1205Wa 0000103946 | yes |  | m² | Zimmer- und Holzbauarbeiten | Wand | Außenwand 2-Schalig | WA-STB |  |  | 7.5 | 1205HWa0000103933 | NEW | no |  | 0 | 0.9 |  | 32 | AllplanAttributes - ash D_Detailverweis: <undefiniert>; Sicherheitsklasse: -; Sonnenschutztyp: Movable; g-Wert: 0,51
 | H2 Ebene +2 | WA-DL | 1205Wa 0000103944 | yes |  | m³ | Zimmer- und Holzbauarbeiten | Wand | Außenwand 2-Schalig | WA-DL |  |  | 7.5 | 1205HWa0000103933 | NEW | no |  | 0 | 0.9 |  | 32 | AllplanAttributes - ash D_Detailverweis: <undefiniert>; Sicherheitsklasse: -; Sonnenschutztyp: Movable; g-Wert: 0,51
 | H2 Ebene +2 | WA-LB | 1205Wa 0000103942 | yes | Codetext | m² | Trockenbauarbeiten | Wand | Außenwand 2-Schalig | WA-LB | 0 | A | 7.5 | 1205HWa0000103933 | NEW | no | yes | 0 | 0.9 | no | 32 | no | Codetext | AllplanAttributes - ash D_Detailverweis: <undefiniert>; Sicherheitsklasse: -; Sonnenschutztyp: Movable; g-Wert: 0,51
 | H2 Ebene +2 | WA-TL | 1205Wa 0000103940 | yes |  | m² | Zimmer- und Holzbauarbeiten | Wand | Außenwand 2-Schalig | WA-TL |  |  | 7.5 | 1205HWa0000103933 | NEW | no |  | 0 | 0.9 |  | 32 | AllplanAttributes - ash D_Detailverweis: <undefiniert>; Sicherheitsklasse: -; Sonnenschutztyp: Movable; g-Wert: 0,51
Traglattung | H2 Ebene +2 | WA-TL | 1205Wa 0000103938 | yes |  | m² | Zimmer- und Holzbauarbeiten | Wand | Traglattung | WA-TL |  |  | 7.5 | 1205HWa0000103933 | NEW | no | yes | 0 | 0.9 |  | 32 | AllplanAttributes - ash D_Detailverweis: <undefiniert>; Sicherheitsklasse: -; Sonnenschutztyp: Movable; g-Wert: 0,51
 | H2 Ebene +2 | WA-HS | 1205Wa 0000103936 | yes |  | m² | Zimmer- und Holzbauarbeiten | Wand | Außenwand 2-Schalig | WA-HS |  |  | 7.5 | 1205HWa0000103933 | NEW | no |  | 0 | 0.9 |  | 32 | AllplanAttributes - ash D_Detailverweis: <undefiniert>; Sicherheitsklasse: -; Sonnenschutztyp: Movable; g-Wert: 0,51
2x Gipsfaserplatte | H2 Ebene +2 | WA-LB | 1205Wa 0000119420 | yes |  | m² | Trockenbauarbeiten | Wand | 2x Gipsfaserplatte | WA-LB |  |  | 7.5 | 1205HWa0000119419 | NEW | no | yes | 0 | 0.9 |  | 32 | AllplanAttributes - ash D_Detailverweis: <undefiniert>; Sicherheitsklasse: -; Sonnenschutztyp: Movable; g-Wert: 0,51
Holzständer + Zwischendämmung | H2 Ebene +2 | WA-HD | 1205Wa 0000119421 | yes |  | m³ | Zimmer- und Holzbauarbeiten | Wand | Holzständer + Zwischendämmung | WA-HD |  |  | 7.5 | 1205HWa0000119419 | NEW | no | yes | 0 | 0.9 |  | 32 | AllplanAttributes - ash D_Detailverweis: <undefiniert>; Sicherheitsklasse: -; Sonnenschutztyp: Movable; g-Wert: 0,51; ash W_laufende Nr. Statik: 2 (W 2.0/ 2.1/ 2.2)
Staffel + Zwischendämmung | H2 Ebene +2 | WA-DL | 1205Wa 0000119422 | yes |  | m³ | Zimmer- und Holzbauarbeiten | Wand | Staffel + Zwischendämmung | WA-DL |  |  | 7.5 | 1205HWa0000119419 | NEW | no | yes | 0 | 0.9 |  | 32 | AllplanAttributes - ash D_Detailverweis: <undefiniert>; Sicherheitsklasse: -; Sonnenschutztyp: Movable; g-Wert: 0,51
 | H2 Ebene +2 | WA-LB | 1205Wa 0000119423 | yes | Codetext | m² | Trockenbauarbeiten | Wand | Außenwand 7-Schalig | WA-LB | 0 | A | 7.5 | 1205HWa0000119419 | NEW | no | yes | 0 | 0.9 | no | 32 | no | Codetext | AllplanAttributes - ash D_Detailverweis: <undefiniert>; Sicherheitsklasse: -; Sonnenschutztyp: Movable; g-Wert: 0,51
Konterlattung | H2 Ebene +2 | WA-KL | 1205Wa 0000119424 | yes |  | m² | Zimmer- und Holzbauarbeiten | Wand | Konterlattung | WA-KL |  |  | 7.5 | 1205HWa0000119419 | NEW | no | yes | 0 | 0.9 |  | 32 | AllplanAttributes - ash D_Detailverweis: <undefiniert>; Sicherheitsklasse: -; Sonnenschutztyp: Movable; g-Wert: 0,51
Traglattung | H2 Ebene +2 | WA-TL | 1205Wa 0000119425 | yes |  | m² | Zimmer- und Holzbauarbeiten | Wand | Traglattung | WA-TL |  |  | 7.5 | 1205HWa0000119419 | NEW | no | yes | 0 | 0.9 |  | 32 | AllplanAttributes - ash D_Detailverweis: <undefiniert>; Sicherheitsklasse: -; Sonnenschutztyp: Movable; g-Wert: 0,51
Holzschindel | H2 Ebene +2 | WA-HS | 1205Wa 0000119426 | yes |  | m² | Zimmer- und Holzbauarbeiten | Wand | Holzschindel | WA-HS |  |  | 7.5 | 1205HWa0000119419 | NEW | no | yes | 0 | 0.9 |  | 32 | AllplanAttributes - ash D_Detailverweis: <undefiniert>; Sicherheitsklasse: -; Sonnenschutztyp: Movable; g-Wert: 0,51
2x Gipsfaserplatte | H2 Ebene +2 | WA-LB | 1205Wa 0000119459 | yes |  | m² | Trockenbauarbeiten | Wand | 2x Gipsfaserplatte | WA-LB |  |  | 7.5 | 1205HWa0000119458 | NEW | no | yes | 0 | 0.9 |  | 32 | AllplanAttributes - ash D_Detailverweis: <undefiniert>; Sicherheitsklasse: -; Sonnenschutztyp: Movable; g-Wert: 0,51
Holzständer + Zwischendämmung | H2 Ebene +2 | WA-HD | 1205Wa 0000119460 | yes |  | m³ | Zimmer- und Holzbauarbeiten | Wand | Holzständer + Zwischendämmung | WA-HD |  |  | 7.5 | 1205HWa0000119458 | NEW | no | yes | 0 | 0.9 |  | 32 | AllplanAttributes - ash D_Detailverweis: <undefiniert>; Sicherheitsklasse: -; Sonnenschutztyp: Movable; g-Wert: 0,51; ash W_laufende Nr. Statik: 2 (W 2.0/ 2.1/ 2.2)
Staffel + Zwischendämmung | H2 Ebene +2 | WA-DL | 1205Wa 0000119461 | yes |  | m³ | Zimmer- und Holzbauarbeiten | Wand | Staffel + Zwischendämmung | WA-DL |  |  | 7.5 | 1205HWa0000119458 | NEW | no | yes | 0 | 0.9 |  | 32 | AllplanAttributes - ash D_Detailverweis: <undefiniert>; Sicherheitsklasse: -; Sonnenschutztyp: Movable; g-Wert: 0,51
 | H2 Ebene +2 | WA-LB | 1205Wa 0000119462 | yes | Codetext | m² | Trockenbauarbeiten | Wand | Außenwand 7-Schalig | WA-LB | 0 | A | 7.5 | 1205HWa0000119458 | NEW | no | yes | 0 | 0.9 | no | 32 | no | Codetext | AllplanAttributes - ash D_Detailverweis: <undefiniert>; Sicherheitsklasse: -; Sonnenschutztyp: Movable; g-Wert: 0,51
Konterlattung | H2 Ebene +2 | WA-KL | 1205Wa 0000119463 | yes |  | m² | Zimmer- und Holzbauarbeiten | Wand | Konterlattung | WA-KL |  |  | 7.5 | 1205HWa0000119458 | NEW | no | yes | 0 | 0.9 |  | 32 | AllplanAttributes - ash D_Detailverweis: <undefiniert>; Sicherheitsklasse: -; Sonnenschutztyp: Movable; g-Wert: 0,51
Traglattung | H2 Ebene +2 | WA-TL | 1205Wa 0000119464 | yes |  | m² | Zimmer- und Holzbauarbeiten | Wand | Traglattung | WA-TL |  |  | 7.5 | 1205HWa0000119458 | NEW | no | yes | 0 | 0.9 |  | 32 | AllplanAttributes - ash D_Detailverweis: <undefiniert>; Sicherheitsklasse: -; Sonnenschutztyp: Movable; g-Wert: 0,51
Holzschindel | H2 Ebene +2 | WA-HS | 1205Wa 0000119465 | yes |  | m² | Zimmer- und Holzbauarbeiten | Wand | Holzschindel | WA-HS |  |  | 7.5 | 1205HWa0000119458 | NEW | no | yes | 0 | 0.9 |  | 32 | AllplanAttributes - ash D_Detailverweis: <undefiniert>; Sicherheitsklasse: -; Sonnenschutztyp: Movable; g-Wert: 0,51
 | H2 Ebene +2 | WA-LB | 1205Wa 0000004865 | yes | Codetext | m² | Trockenbauarbeiten | Wand | Außenwand 7-Schalig | WA-LB | 0 | A | 7.5 | 1205HWa0000004158 | NEW | no | yes | 0 | 0.9 | no | - | no | Codetext | AllplanAttributes - ash D_Detailverweis: <undefiniert>; Sicherheitsklasse: -; Sonnenschutztyp: Movable; g-Wert: 0,51
 | H2 Ebene +2 | WA-DL | 1205Wa 0000004860 | yes | Codetext | m³ | Zimmer- und Holzbauarbeiten | Wand | Außenwand 7-Schalig | WA-DL | 0 | A | 7.5 | 1205HWa0000004158 | NEW | no | yes | 0 | 0.9 | no | - | no | Codetext | AllplanAttributes - ash D_Detailverweis: <undefiniert>; Sicherheitsklasse: -; Sonnenschutztyp: Movable; g-Wert: 0,51; ash W_laufende Nr. Statik: 2 (W 2.0/ 2.1/ 2.2)
 | H2 Ebene +2 | WA-DL | 1205Wa 0000004855 | yes | Codetext | m³ | Zimmer- und Holzbauarbeiten | Wand | Außenwand 7-Schalig | WA-DL | 0 | A | 7.5 | 1205HWa0000004158 | NEW | no | yes | 0 | 0.9 | no | - | no | Codetext | AllplanAttributes - ash D_Detailverweis: <undefiniert>; Sicherheitsklasse: -; Sonnenschutztyp: Movable; g-Wert: 0,51
 | H2 Ebene +2 | WA-LB | 1205Wa 0000004850 | yes | Codetext | m² | Trockenbauarbeiten | Wand | Außenwand 7-Schalig | WA-LB | 0 | A | 7.5 | 1205HWa0000004158 | NEW | no | yes | 0 | 0.9 | no | - | no | Codetext | AllplanAttributes - ash D_Detailverweis: <undefiniert>; Sicherheitsklasse: -; Sonnenschutztyp: Movable; g-Wert: 0,51
 | H2 Ebene +2 | WA-KL | 1205Wa 0000004845 | yes | Codetext | m² | Zimmer- und Holzbauarbeiten | Wand | Außenwand 7-Schalig | WA-KL | 0 | A | 7.5 | 1205HWa0000004158 | NEW | no | yes | 0 | 0.9 | no | - | no | Codetext | AllplanAttributes - ash D_Detailverweis: <undefiniert>; Sicherheitsklasse: -; Sonnenschutztyp: Movable; g-Wert: 0,51
 | H2 Ebene +2 | WA-TL | 1205Wa 0000004840 | yes | Codetext | m² | Zimmer- und Holzbauarbeiten | Wand | Außenwand 7-Schalig | WA-TL | 0 | A | 7.5 | 1205HWa0000004158 | NEW | no | yes | 0 | 0.9 | no | - | no | Codetext | AllplanAttributes - ash D_Detailverweis: <undefiniert>; Sicherheitsklasse: -; Sonnenschutztyp: Movable; g-Wert: 0,51
 | H2 Ebene +2 | WA-HS | 1205Wa 0000004835 | yes | Codetext | m² | Zimmer- und Holzbauarbeiten | Wand | Außenwand 7-Schalig | WA-HS | 0 | A | 7.5 | 1205HWa0000004158 | NEW | no | yes | 0 | 0.9 | no | - | no | Codetext | AllplanAttributes - ash D_Detailverweis: <undefiniert>; Sicherheitsklasse: -; Sonnenschutztyp: Movable; g-Wert: 0,51
 | H2 Ebene +2 | WA-LB | 1205Wa 0000004538 | yes | Codetext | m² | Trockenbauarbeiten | Wand | Außenwand 7-Schalig | WA-LB | 0 | A | 7.5 | 1205HWa0000004048 | NEW | no | yes | 0 | 0.9 | no | 32 | no | Codetext | AllplanAttributes - ash D_Detailverweis: <undefiniert>; Sicherheitsklasse: -; Sonnenschutztyp: Movable; g-Wert: 0,51
 | H2 Ebene +2 | WA-DL | 1205Wa 0000004543 | yes | Codetext | m³ | Zimmer- und Holzbauarbeiten | Wand | Außenwand 7-Schalig | WA-DL | 0 | A | 7.5 | 1205HWa0000004048 | NEW | no | yes | 0 | 0.9 | no | 32 | no | Codetext | AllplanAttributes - ash D_Detailverweis: <undefiniert>; Sicherheitsklasse: -; Sonnenschutztyp: Movable; g-Wert: 0,51; ash W_laufende Nr. Statik: 2 (W 2.0/ 2.1/ 2.2)
 | H2 Ebene +2 | WA-DL | 1205Wa 0000004548 | yes | Codetext | m³ | Zimmer- und Holzbauarbeiten | Wand | Außenwand 7-Schalig | WA-DL | 0 | A | 7.5 | 1205HWa0000004048 | NEW | no | yes | 0 | 0.9 | no | 32 | no | Codetext | AllplanAttributes - ash D_Detailverweis: <undefiniert>; Sicherheitsklasse: -; Sonnenschutztyp: Movable; g-Wert: 0,51
 | H2 Ebene +2 | WA-LB | 1205Wa 0000004553 | yes | Codetext | m² | Trockenbauarbeiten | Wand | Außenwand 7-Schalig | WA-LB | 0 | A | 7.5 | 1205HWa0000004048 | NEW | no | yes | 0 | 0.9 | no | 32 | no | Codetext | AllplanAttributes - ash D_Detailverweis: <undefiniert>; Sicherheitsklasse: -; Sonnenschutztyp: Movable; g-Wert: 0,51
 | H2 Ebene +2 | WA-KL | 1205Wa 0000004558 | yes | Codetext | m² | Zimmer- und Holzbauarbeiten | Wand | Außenwand 7-Schalig | WA-KL | 0 | A | 7.5 | 1205HWa0000004048 | NEW | no | yes | 0 | 0.9 | no | 32 | no | Codetext | AllplanAttributes - ash D_Detailverweis: <undefiniert>; Sicherheitsklasse: -; Sonnenschutztyp: Movable; g-Wert: 0,51
 | H2 Ebene +2 | WA-TL | 1205Wa 0000004563 | yes | Codetext | m² | Zimmer- und Holzbauarbeiten | Wand | Außenwand 7-Schalig | WA-TL | 0 | A | 7.5 | 1205HWa0000004048 | NEW | no | yes | 0 | 0.9 | no | 32 | no | Codetext | AllplanAttributes - ash D_Detailverweis: <undefiniert>; Sicherheitsklasse: -; Sonnenschutztyp: Movable; g-Wert: 0,51
 | H2 Ebene +2 | WA-HS | 1205Wa 0000004568 | yes | Codetext | m² | Zimmer- und Holzbauarbeiten | Wand | Außenwand 7-Schalig | WA-HS | 0 | A | 7.5 | 1205HWa0000004048 | NEW | no | yes | 0 | 0.9 | no | 32 | no | Codetext | AllplanAttributes - ash D_Detailverweis: <undefiniert>; Sicherheitsklasse: -; Sonnenschutztyp: Movable; g-Wert: 0,51
 | H2 Ebene +2 | WA-LB | 1205Wa 0000180852 | yes | Codetext | m² | Trockenbauarbeiten | Wand | Außenwand 7-Schalig | WA-LB | 0 | A | 7.5 | 1205HWa0000180744 | NEW | no | yes | 0 | 0.9 | no | 32 | no | Codetext | AllplanAttributes - ash D_Detailverweis: <undefiniert>; Sicherheitsklasse: -; Sonnenschutztyp: Movable; g-Wert: 0,51
 | H2 Ebene +2 | WA-HD | 1205Wa 0000180851 | yes | Codetext | m³ | Zimmer- und Holzbauarbeiten | Wand | Außenwand 7-Schalig | WA-HD | 0 | A | 7.5 | 1205HWa0000180744 | NEW | no | yes | 0 | 0.9 | no | 32 | no | Codetext | AllplanAttributes - ash D_Detailverweis: <undefiniert>; Sicherheitsklasse: -; Sonnenschutztyp: Movable; g-Wert: 0,51; ash W_laufende Nr. Statik: 2 (W 2.0/ 2.1/ 2.2)
 | H2 Ebene +2 | WA-DL | 1205Wa 0000180850 | yes | Codetext | m³ | Zimmer- und Holzbauarbeiten | Wand | Außenwand 7-Schalig | WA-DL | 0 | A | 7.5 | 1205HWa0000180744 | NEW | no | yes | 0 | 0.9 | no | 32 | no | Codetext | AllplanAttributes - ash D_Detailverweis: <undefiniert>; Sicherheitsklasse: -; Sonnenschutztyp: Movable; g-Wert: 0,51
 | H2 Ebene +2 | WA-LB | 1205Wa 0000180849 | yes | Codetext | m² | Trockenbauarbeiten | Wand | Außenwand 7-Schalig | WA-LB | 0 | A | 7.5 | 1205HWa0000180744 | NEW | no | yes | 0 | 0.9 | no | 32 | no | Codetext | AllplanAttributes - ash D_Detailverweis: <undefiniert>; Sicherheitsklasse: -; Sonnenschutztyp: Movable; g-Wert: 0,51
 | H2 Ebene +2 | WA-KL | 1205Wa 0000180848 | yes | Codetext | m² | Zimmer- und Holzbauarbeiten | Wand | Außenwand 7-Schalig | WA-KL | 0 | A | 7.5 | 1205HWa0000180744 | NEW | no | yes | 0 | 0.9 | no | 32 | no | Codetext | AllplanAttributes - ash D_Detailverweis: <undefiniert>; Sicherheitsklasse: -; Sonnenschutztyp: Movable; g-Wert: 0,51
 | H2 Ebene +2 | WA-TL | 1205Wa 0000180847 | yes | Codetext | m² | Zimmer- und Holzbauarbeiten | Wand | Außenwand 7-Schalig | WA-TL | 0 | A | 7.5 | 1205HWa0000180744 | NEW | no | yes | 0 | 0.9 | no | 32 | no | Codetext | AllplanAttributes - ash D_Detailverweis: <undefiniert>; Sicherheitsklasse: -; Sonnenschutztyp: Movable; g-Wert: 0,51
 | H2 Ebene +2 | WA-HS | 1205Wa 0000180846 | yes | Codetext | m² | Zimmer- und Holzbauarbeiten | Wand | Außenwand 7-Schalig | WA-HS | 0 | A | 7.5 | 1205HWa0000180744 | NEW | no | yes | 0 | 0.9 | no | 32 | no | Codetext | AllplanAttributes - ash D_Detailverweis: <undefiniert>; Sicherheitsklasse: -; Sonnenschutztyp: Movable; g-Wert: 0,51
2x Gipsfaserplatte | H2 Ebene +2 | WA-LB | 1205Wa 0000183508 | yes |  | m² | Trockenbauarbeiten | Wand | 2x Gipsfaserplatte | WA-LB |  |  | 7.5 | 1205HWa0000183438 | NEW | no | yes | 0 | 0.9 |  | - | AllplanAttributes - ash D_Detailverweis: <undefiniert>; Sicherheitsklasse: -; Sonnenschutztyp: Movable; g-Wert: 0,51
Holzständer + Zwischendämmung | H2 Ebene +2 | WA-HD | 1205Wa 0000183507 | yes |  | m³ | Zimmer- und Holzbauarbeiten | Wand | Holzständer + Zwischendämmung | WA-HD |  |  | 7.5 | 1205HWa0000183438 | NEW | no | yes | 0 | 0.9 |  | - | AllplanAttributes - ash D_Detailverweis: DT D; ash D_Plannummer: D1851; Sicherheitsklasse: -; Sonnenschutztyp: Movable; g-Wert: 0,51; ash W_laufende Nr. Statik: 5 (W 4.0)
Staffel + Zwischendämmung | H2 Ebene +2 | WA-DL | 1205Wa 0000183506 | yes |  | m³ | Zimmer- und Holzbauarbeiten | Wand | Staffel + Zwischendämmung | WA-DL |  |  | 7.5 | 1205HWa0000183438 | NEW | no | yes | 0 | 0.9 |  | - | AllplanAttributes - ash D_Detailverweis: <undefiniert>; Sicherheitsklasse: -; Sonnenschutztyp: Movable; g-Wert: 0,51
 | H2 Ebene +2 | WA-LB | 1205Wa 0000183505 | yes | Codetext | m² | Trockenbauarbeiten | Wand | Außenwand 7-Schalig | WA-LB | 0 | A | 7.5 | 1205HWa0000183438 | NEW | no | yes | 0 | 0.9 | no | - | no | Codetext | AllplanAttributes - ash D_Detailverweis: <undefiniert>; Sicherheitsklasse: -; Sonnenschutztyp: Movable; g-Wert: 0,51
Konterlattung | H2 Ebene +2 | WA-KL | 1205Wa 0000183504 | yes |  | m² | Zimmer- und Holzbauarbeiten | Wand | Konterlattung | WA-KL |  |  | 7.5 | 1205HWa0000183438 | NEW | no | yes | 0 | 0.9 |  | - | AllplanAttributes - ash D_Detailverweis: <undefiniert>; Sicherheitsklasse: -; Sonnenschutztyp: Movable; g-Wert: 0,51
Traglattung | H2 Ebene +2 | WA-TL | 1205Wa 0000183503 | yes |  | m² | Zimmer- und Holzbauarbeiten | Wand | Traglattung | WA-TL |  |  | 7.5 | 1205HWa0000183438 | NEW | no | yes | 0 | 0.9 |  | - | AllplanAttributes - ash D_Detailverweis: <undefiniert>; Sicherheitsklasse: -; Sonnenschutztyp: Movable; g-Wert: 0,51
Holzschindel | H2 Ebene +2 | WA-HS | 1205Wa 0000183502 | yes |  | m² | Zimmer- und Holzbauarbeiten | Wand | Holzschindel | WA-HS |  |  | 7.5 | 1205HWa0000183438 | NEW | no | yes | 0 | 0.9 |  | - | AllplanAttributes - ash D_Detailverweis: <undefiniert>; Sicherheitsklasse: -; Sonnenschutztyp: Movable; g-Wert: 0,51
 | H2 Ebene +2 | WA-LB | 1205Wa 0000005300 | yes | Codetext | m² | Trockenbauarbeiten | Wand | Außenwand 7-Schalig | WA-LB | 0 | A | 7.5 | 1205HWa0000003236 | NEW | no | yes | 0 | 0.9 | no | 32 | no | Codetext | AllplanAttributes - ash D_Detailverweis: <undefiniert>; Sicherheitsklasse: -; Sonnenschutztyp: Movable; g-Wert: 0,51
 | H2 Ebene +2 | WA-DL | 1205Wa 0000005290 | yes | Codetext | m³ | Zimmer- und Holzbauarbeiten | Wand | Außenwand 7-Schalig | WA-DL | 0 | A | 7.5 | 1205HWa0000003236 | NEW | no | yes | 0 | 0.9 | no | 32 | no | Codetext | AllplanAttributes - ash D_Detailverweis: DT D; ash D_Plannummer: D1851; Sicherheitsklasse: -; Sonnenschutztyp: Movable; g-Wert: 0,51; ash W_laufende Nr. Statik: 2 (W 2.0/ 2.1/ 2.2)
 | H2 Ebene +2 | WA-DL | 1205Wa 0000005280 | yes | Codetext | m³ | Zimmer- und Holzbauarbeiten | Wand | Außenwand 7-Schalig | WA-DL | 0 | A | 7.5 | 1205HWa0000003236 | NEW | no | yes | 0 | 0.9 | no | 32 | no | Codetext | AllplanAttributes - ash D_Detailverweis: <undefiniert>; Sicherheitsklasse: -; Sonnenschutztyp: Movable; g-Wert: 0,51
 | H2 Ebene +2 | WA-LB | 1205Wa 0000005270 | yes | Codetext | m² | Trockenbauarbeiten | Wand | Außenwand 7-Schalig | WA-LB | 0 | A | 7.5 | 1205HWa0000003236 | NEW | no | yes | 0 | 0.9 | no | 32 | no | Codetext | AllplanAttributes - ash D_Detailverweis: <undefiniert>; Sicherheitsklasse: -; Sonnenschutztyp: Movable; g-Wert: 0,51
 | H2 Ebene +2 | WA-KL | 1205Wa 0000005260 | yes | Codetext | m² | Zimmer- und Holzbauarbeiten | Wand | Außenwand 7-Schalig | WA-KL | 0 | A | 7.5 | 1205HWa0000003236 | NEW | no | yes | 0 | 0.9 | no | 32 | no | Codetext | AllplanAttributes - ash D_Detailverweis: <undefiniert>; Sicherheitsklasse: -; Sonnenschutztyp: Movable; g-Wert: 0,51
 | H2 Ebene +2 | WA-TL | 1205Wa 0000005250 | yes | Codetext | m² | Zimmer- und Holzbauarbeiten | Wand | Außenwand 7-Schalig | WA-TL | 0 | A | 7.5 | 1205HWa0000003236 | NEW | no | yes | 0 | 0.9 | no | 32 | no | Codetext | AllplanAttributes - ash D_Detailverweis: <undefiniert>; Sicherheitsklasse: -; Sonnenschutztyp: Movable; g-Wert: 0,51
 | H2 Ebene +2 | WA-HS | 1205Wa 0000005240 | yes | Codetext | m² | Zimmer- und Holzbauarbeiten | Wand | Außenwand 7-Schalig | WA-HS | 0 | A | 7.5 | 1205HWa0000003236 | NEW | no | yes | 0 | 0.9 | no | 32 | no | Codetext | AllplanAttributes - ash D_Detailverweis: <undefiniert>; Sicherheitsklasse: -; Sonnenschutztyp: Movable; g-Wert: 0,51
 | H2 Ebene +2 | WA-LB | 1205Wa 0000002019 | yes | Codetext | m² | Trockenbauarbeiten | Wand | Außenwand 7-Schalig | WA-LB | 0 | A | 7.5 | 1205HWa0000001927 | NEW | no | yes | 0 | 0.9 | no | 32 | no | Codetext | AllplanAttributes - ash D_Detailverweis: <undefiniert>; Sicherheitsklasse: -; Sonnenschutztyp: Movable; g-Wert: 0,51
 | H2 Ebene +2 | WA-HD | 1205Wa 0000002017 | yes | Codetext | m³ | Zimmer- und Holzbauarbeiten | Wand | Außenwand 7-Schalig | WA-HD | 0 | A | 7.5 | 1205HWa0000001927 | NEW | no | yes | 0 | 0.9 | no | 32 | no | Codetext | AllplanAttributes - ash D_Detailverweis: <undefiniert>; Sicherheitsklasse: -; Sonnenschutztyp: Movable; g-Wert: 0,51; ash W_laufende Nr. Statik: 5 (W 4.0)
 | H2 Ebene +2 | WA-DL | 1205Wa 0000002015 | yes | Codetext | m³ | Zimmer- und Holzbauarbeiten | Wand | Außenwand 7-Schalig | WA-DL | 0 | A | 7.5 | 1205HWa0000001927 | NEW | no | yes | 0 | 0.9 | no | 32 | no | Codetext | AllplanAttributes - ash D_Detailverweis: <undefiniert>; Sicherheitsklasse: -; Sonnenschutztyp: Movable; g-Wert: 0,51
 | H2 Ebene +2 | WA-LB | 1205Wa 0000002013 | yes | Codetext | m² | Trockenbauarbeiten | Wand | Außenwand 7-Schalig | WA-LB | 0 | A | 7.5 | 1205HWa0000001927 | NEW | no | yes | 0 | 0.9 | no | 32 | no | Codetext | AllplanAttributes - ash D_Detailverweis: <undefiniert>; Sicherheitsklasse: -; Sonnenschutztyp: Movable; g-Wert: 0,51
 | H2 Ebene +2 | WA-KL | 1205Wa 0000002011 | yes | Codetext | m² | Zimmer- und Holzbauarbeiten | Wand | Außenwand 7-Schalig | WA-KL | 0 | A | 7.5 | 1205HWa0000001927 | NEW | no | yes | 0 | 0.9 | no | 32 | no | Codetext | AllplanAttributes - ash D_Detailverweis: <undefiniert>; Sicherheitsklasse: -; Sonnenschutztyp: Movable; g-Wert: 0,51
 | H2 Ebene +2 | WA-TL | 1205Wa 0000002009 | yes | Codetext | m² | Zimmer- und Holzbauarbeiten | Wand | Außenwand 7-Schalig | WA-TL | 0 | A | 7.5 | 1205HWa0000001927 | NEW | no | yes | 0 | 0.9 | no | 32 | no | Codetext | AllplanAttributes - ash D_Detailverweis: <undefiniert>; Sicherheitsklasse: -; Sonnenschutztyp: Movable; g-Wert: 0,51
 | H2 Ebene +2 | WA-HS | 1205Wa 0000002007 | yes | Codetext | m² | Zimmer- und Holzbauarbeiten | Wand | Außenwand 7-Schalig | WA-HS | 0 | A | 7.5 | 1205HWa0000001927 | NEW | no | yes | 0 | 0.9 | no | 32 | no | Codetext | AllplanAttributes - ash D_Detailverweis: <undefiniert>; Sicherheitsklasse: -; Sonnenschutztyp: Movable; g-Wert: 0,51
 | H2 Ebene +2 | WA-LB | 1205Wa 0000258744 | yes | Codetext | m² | Trockenbauarbeiten | Wand | Außenwand 7-Schalig | WA-LB | 0 | A | 7.5 | 1205HWa0000182914 | NEW | no | yes | 0 | 0.9 | no | 32 | no | Codetext | AllplanAttributes - ash D_Detailverweis: <undefiniert>; Sicherheitsklasse: -; Sonnenschutztyp: Movable; g-Wert: 0,51
2x Gipsfaserplatte | H2 Ebene +2 | WA-LB | 1205Wa 0000258743 | yes |  | m² | Trockenbauarbeiten | Wand | 2x Gipsfaserplatte | WA-LB |  |  | 7.5 | 1205HWa0000182914 | NEW | no | yes | 0 | 0.9 |  | 32 | AllplanAttributes - ash D_Detailverweis: <undefiniert>; Sicherheitsklasse: -; Sonnenschutztyp: Movable; g-Wert: 0,51
 | H2 Ebene +2 | WA-HD | 1205Wa 0000258742 | yes | Codetext | m³ | Zimmer- und Holzbauarbeiten | Wand | Außenwand 7-Schalig | WA-HD | 0 | A | 7.5 | 1205HWa0000182914 | NEW | no | yes | 0 | 0.9 | no | 32 | no | Codetext | AllplanAttributes - ash D_Detailverweis: DT A; ash D_Plannummer: D1850; Sicherheitsklasse: -; Sonnenschutztyp: Movable; g-Wert: 0,51; ash W_laufende Nr. Statik: 6 (W 6.0)
 | H2 Ebene +2 | WA-LB | 1205Wa 0000258741 | yes | Codetext | m² | Trockenbauarbeiten | Wand | Außenwand 7-Schalig | WA-LB | 0 | A | 7.5 | 1205HWa0000182914 | NEW | no | yes | 0 | 0.9 | no | 32 | no | Codetext | AllplanAttributes - ash D_Detailverweis: <undefiniert>; Sicherheitsklasse: -; Sonnenschutztyp: Movable; g-Wert: 0,51
 | H2 Ebene +2 | WA-LB | 1205Wa 0000258740 | yes | Codetext | m² | Trockenbauarbeiten | Wand | Außenwand 7-Schalig | WA-LB | 0 | A | 7.5 | 1205HWa0000182914 | NEW | no | yes | 0 | 0.9 | no | 32 | no | Codetext | AllplanAttributes - ash D_Detailverweis: <undefiniert>; Sicherheitsklasse: -; Sonnenschutztyp: Movable; g-Wert: 0,51
 | H2 Ebene +2 | WA-DL | 1205Wa 0000258739 | yes | Codetext | m³ | Zimmer- und Holzbauarbeiten | Wand | Außenwand 7-Schalig | WA-DL | 0 | A | 7.5 | 1205HWa0000182914 | NEW | no | yes | 0 | 0.9 | no | 32 | no | Codetext | AllplanAttributes - ash D_Detailverweis: <undefiniert>; Sicherheitsklasse: -; Sonnenschutztyp: Movable; g-Wert: 0,51
 | H2 Ebene +2 | WA-KL | 1205Wa 0000258738 | yes | Codetext | m² | Zimmer- und Holzbauarbeiten | Wand | Außenwand 7-Schalig | WA-KL | 0 | A | 7.5 | 1205HWa0000182914 | NEW | no | yes | 0 | 0.9 | no | 32 | no | Codetext | AllplanAttributes - ash D_Detailverweis: <undefiniert>; Sicherheitsklasse: -; Sonnenschutztyp: Movable; g-Wert: 0,51
 | H2 Ebene +2 | WA-TL | 1205Wa 0000258737 | yes | Codetext | m² | Zimmer- und Holzbauarbeiten | Wand | Außenwand 7-Schalig | WA-TL | 0 | A | 7.5 | 1205HWa0000182914 | NEW | no | yes | 0 | 0.9 | no | 32 | no | Codetext | AllplanAttributes - ash D_Detailverweis: <undefiniert>; Sicherheitsklasse: -; Sonnenschutztyp: Movable; g-Wert: 0,51
 | H2 Ebene +2 | WA-HS | 1205Wa 0000258736 | yes | Codetext | m² | Zimmer- und Holzbauarbeiten | Wand | Außenwand 7-Schalig | WA-HS | 0 | A | 7.5 | 1205HWa0000182914 | NEW | no | yes | 0 | 0.9 | no | 32 | no | Codetext | AllplanAttributes - ash D_Detailverweis: <undefiniert>; Sicherheitsklasse: -; Sonnenschutztyp: Movable; g-Wert: 0,51
 | H2 Ebene +2 | WA-LB | 1205Wa 0000259456 | yes | Codetext | m² | Trockenbauarbeiten | Wand | Außenwand 7-Schalig | WA-LB | 0 | A | 7.5 | 1205HWa0000182410 | NEW | no | yes | 0 | 0.9 | no | 32 | no | Codetext | AllplanAttributes - ash D_Detailverweis: <undefiniert>; Sicherheitsklasse: -; Sonnenschutztyp: Movable; g-Wert: 0,51
 | H2 Ebene +2 | WA-HD | 1205Wa 0000259455 | yes | Codetext | m³ | Zimmer- und Holzbauarbeiten | Wand | Außenwand 7-Schalig | WA-HD | 0 | A | 7.5 | 1205HWa0000182410 | NEW | no | yes | 0 | 0.9 | no | 32 | no | Codetext | AllplanAttributes - ash D_Detailverweis: <undefiniert>; Sicherheitsklasse: -; Sonnenschutztyp: Movable; g-Wert: 0,51; ash W_laufende Nr. Statik: 2 (W 2.0/ 2.1/ 2.2)
 | H2 Ebene +2 | WA-DL | 1205Wa 0000259454 | yes | Codetext | m³ | Zimmer- und Holzbauarbeiten | Wand | Außenwand 7-Schalig | WA-DL | 0 | A | 7.5 | 1205HWa0000182410 | NEW | no | yes | 0 | 0.9 | no | 32 | no | Codetext | AllplanAttributes - ash D_Detailverweis: <undefiniert>; Sicherheitsklasse: -; Sonnenschutztyp: Movable; g-Wert: 0,51
 | H2 Ebene +2 | WA-LB | 1205Wa 0000259453 | yes | Codetext | m² | Trockenbauarbeiten | Wand | Außenwand 7-Schalig | WA-LB | 0 | A | 7.5 | 1205HWa0000182410 | NEW | no | yes | 0 | 0.9 | no | 32 | no | Codetext | AllplanAttributes - ash D_Detailverweis: <undefiniert>; Sicherheitsklasse: -; Sonnenschutztyp: Movable; g-Wert: 0,51
 | H2 Ebene +2 | WA-KL | 1205Wa 0000259452 | yes | Codetext | m² | Zimmer- und Holzbauarbeiten | Wand | Außenwand 7-Schalig | WA-KL | 0 | A | 7.5 | 1205HWa0000182410 | NEW | no | yes | 0 | 0.9 | no | 32 | no | Codetext | AllplanAttributes - ash D_Detailverweis: <undefiniert>; Sicherheitsklasse: -; Sonnenschutztyp: Movable; g-Wert: 0,51
 | H2 Ebene +2 | WA-TL | 1205Wa 0000259451 | yes | Codetext | m² | Zimmer- und Holzbauarbeiten | Wand | Außenwand 7-Schalig | WA-TL | 0 | A | 7.5 | 1205HWa0000182410 | NEW | no | yes | 0 | 0.9 | no | 32 | no | Codetext | AllplanAttributes - ash D_Detailverweis: <undefiniert>; Sicherheitsklasse: -; Sonnenschutztyp: Movable; g-Wert: 0,51
 | H2 Ebene +2 | WA-HS | 1205Wa 0000259450 | yes | Codetext | m² | Zimmer- und Holzbauarbeiten | Wand | Außenwand 7-Schalig | WA-HS | 0 | A | 7.5 | 1205HWa0000182410 | NEW | no | yes | 0 | 0.9 | no | 32 | no | Codetext | AllplanAttributes - ash D_Detailverweis: <undefiniert>; Sicherheitsklasse: -; Sonnenschutztyp: Movable; g-Wert: 0,51
2x Gipsfaserplatte | H2 Ebene +2 | WA-LB | 1205Wa 0000181433 | yes |  | m² | Trockenbauarbeiten | Wand | 2x Gipsfaserplatte | WA-LB |  |  | 7.5 | 1205HWa0000181423 | NEW | no | yes | 0 | 0.9 |  | 32 | AllplanAttributes - ash D_Detailverweis: <undefiniert>; Sicherheitsklasse: -; Sonnenschutztyp: Movable; g-Wert: 0,51
2x Gipsfaserplatte | H2 Ebene +2 | WA-LB | 1205Wa 0000181432 | yes |  | m² | Trockenbauarbeiten | Wand | 2x Gipsfaserplatte | WA-LB |  |  | 7.5 | 1205HWa0000181423 | NEW | no | yes | 0 | 0.9 |  | 32 | AllplanAttributes - ash D_Detailverweis: <undefiniert>; Sicherheitsklasse: -; Sonnenschutztyp: Movable; g-Wert: 0,51
Holzständer + Zwischendämmung | H2 Ebene +2 | WA-HD | 1205Wa 0000181431 | yes |  | m³ | Zimmer- und Holzbauarbeiten | Wand | Holzständer + Zwischendämmung | WA-HD |  |  | 7.5 | 1205HWa0000181423 | NEW | no | yes | 0 | 0.9 |  | 32 | AllplanAttributes - ash D_Detailverweis: <undefiniert>; Sicherheitsklasse: -; Sonnenschutztyp: Movable; g-Wert: 0,51; ash W_laufende Nr. Statik: 6 (W 6.0)
 | H2 Ebene +2 | WA-LB | 1205Wa 0000181430 | yes | Codetext | m² | Trockenbauarbeiten | Wand | Außenwand 7-Schalig | WA-LB | 0 | A | 7.5 | 1205HWa0000181423 | NEW | no | yes | 0 | 0.9 | no | 32 | no | Codetext | AllplanAttributes - ash D_Detailverweis: <undefiniert>; Sicherheitsklasse: -; Sonnenschutztyp: Movable; g-Wert: 0,51
 | H2 Ebene +2 | WA-LB | 1205Wa 0000181429 | yes | Codetext | m² | Trockenbauarbeiten | Wand | Außenwand 7-Schalig | WA-LB | 0 | A | 7.5 | 1205HWa0000181423 | NEW | no | yes | 0 | 0.9 | no | 32 | no | Codetext | AllplanAttributes - ash D_Detailverweis: <undefiniert>; Sicherheitsklasse: -; Sonnenschutztyp: Movable; g-Wert: 0,51
Staffel + Zwischendämmung | H2 Ebene +2 | WA-DL | 1205Wa 0000181428 | yes |  | m³ | Zimmer- und Holzbauarbeiten | Wand | Staffel + Zwischendämmung | WA-DL |  |  | 7.5 | 1205HWa0000181423 | NEW | no | yes | 0 | 0.9 |  | 32 | AllplanAttributes - ash D_Detailverweis: <undefiniert>; Sicherheitsklasse: -; Sonnenschutztyp: Movable; g-Wert: 0,51
Konterlattung | H2 Ebene +2 | WA-KL | 1205Wa 0000181427 | yes |  | m² | Zimmer- und Holzbauarbeiten | Wand | Konterlattung | WA-KL |  |  | 7.5 | 1205HWa0000181423 | NEW | no | yes | 0 | 0.9 |  | 32 | AllplanAttributes - ash D_Detailverweis: <undefiniert>; Sicherheitsklasse: -; Sonnenschutztyp: Movable; g-Wert: 0,51
Traglattung | H2 Ebene +2 | WA-TL | 1205Wa 0000181426 | yes |  | m² | Zimmer- und Holzbauarbeiten | Wand | Traglattung | WA-TL |  |  | 7.5 | 1205HWa0000181423 | NEW | no | yes | 0 | 0.9 |  | 32 | AllplanAttributes - ash D_Detailverweis: <undefiniert>; Sicherheitsklasse: -; Sonnenschutztyp: Movable; g-Wert: 0,51
Holzschindel | H2 Ebene +2 | WA-HS | 1205Wa 0000181425 | yes |  | m² | Zimmer- und Holzbauarbeiten | Wand | Holzschindel | WA-HS |  |  | 7.5 | 1205HWa0000181423 | NEW | no | yes | 0 | 0.9 |  | 32 | AllplanAttributes - ash D_Detailverweis: <undefiniert>; Sicherheitsklasse: -; Sonnenschutztyp: Movable; g-Wert: 0,51
2x Gipsfaserplatte | H2 Ebene +2 | WA-LB | 1205Wa 0000004356 | yes |  | m² | Trockenbauarbeiten | Wand | 2x Gipsfaserplatte | WA-LB |  |  | 7.5 | 1205HWa0000004285 | NEW | no | yes | 0 | 0.9 |  | 32 | AllplanAttributes - ash D_Detailverweis: <undefiniert>; Sicherheitsklasse: -; Sonnenschutztyp: Movable; g-Wert: 0,51
2x Gipsfaserplatte | H2 Ebene +2 | WA-LB | 1205Wa 0000004360 | yes |  | m² | Trockenbauarbeiten | Wand | 2x Gipsfaserplatte | WA-LB |  |  | 7.5 | 1205HWa0000004285 | NEW | no | yes | 0 | 0.9 |  | 32 | AllplanAttributes - ash D_Detailverweis: <undefiniert>; Sicherheitsklasse: -; Sonnenschutztyp: Movable; g-Wert: 0,51
Holzständer + Zwischendämmung | H2 Ebene +2 | WA-HD | 1205Wa 0000004364 | yes |  | m³ | Zimmer- und Holzbauarbeiten | Wand | Holzständer + Zwischendämmung | WA-HD |  |  | 7.5 | 1205HWa0000004285 | NEW | no | yes | 0 | 0.9 |  | 32 | AllplanAttributes - ash D_Detailverweis: <undefiniert>; Sicherheitsklasse: -; Sonnenschutztyp: Movable; g-Wert: 0,51
 | H2 Ebene +2 | WA-LB | 1205Wa 0000004368 | yes | Codetext | m² | Trockenbauarbeiten | Wand | Außenwand 7-Schalig | WA-LB | 0 | A | 7.5 | 1205HWa0000004285 | NEW | no | yes | 0 | 0.9 | no | 32 | no | Codetext | AllplanAttributes - ash D_Detailverweis: <undefiniert>; Sicherheitsklasse: -; Sonnenschutztyp: Movable; g-Wert: 0,51
 | H2 Ebene +2 | WA-LB | 1205Wa 0000004372 | yes | Codetext | m² | Trockenbauarbeiten | Wand | Außenwand 7-Schalig | WA-LB | 0 | A | 7.5 | 1205HWa0000004285 | NEW | no | yes | 0 | 0.9 | no | 32 | no | Codetext | AllplanAttributes - ash D_Detailverweis: <undefiniert>; Sicherheitsklasse: -; Sonnenschutztyp: Movable; g-Wert: 0,51
Staffel + Zwischendämmung | H2 Ebene +2 | WA-DL | 1205Wa 0000004376 | yes |  | m³ | Zimmer- und Holzbauarbeiten | Wand | Staffel + Zwischendämmung | WA-DL |  |  | 7.5 | 1205HWa0000004285 | NEW | no | yes | 0 | 0.9 |  | 32 | AllplanAttributes - ash D_Detailverweis: <undefiniert>; Sicherheitsklasse: -; Sonnenschutztyp: Movable; g-Wert: 0,51
Konterlattung | H2 Ebene +2 | WA-KL | 1205Wa 0000004380 | yes |  | m² | Zimmer- und Holzbauarbeiten | Wand | Konterlattung | WA-KL |  |  | 7.5 | 1205HWa0000004285 | NEW | no | yes | 0 | 0.9 |  | 32 | AllplanAttributes - ash D_Detailverweis: <undefiniert>; Sicherheitsklasse: -; Sonnenschutztyp: Movable; g-Wert: 0,51
Traglattung | H2 Ebene +2 | WA-TL | 1205Wa 0000144496 | yes |  | m² | Zimmer- und Holzbauarbeiten | Wand | Traglattung | WA-TL |  |  | 7.5 | 1205HWa0000004285 | NEW | no | yes | 0 | 0.9 |  | 32 | AllplanAttributes - ash D_Detailverweis: <undefiniert>; Sicherheitsklasse: -; Sonnenschutztyp: Movable; g-Wert: 0,51
Holzschindel | H2 Ebene +2 | WA-HS | 1205Wa 0000144497 | yes |  | m² | Zimmer- und Holzbauarbeiten | Wand | Holzschindel | WA-HS |  |  | 7.5 | 1205HWa0000004285 | NEW | no | yes | 0 | 0.9 |  | 32 | AllplanAttributes - ash D_Detailverweis: <undefiniert>; Sicherheitsklasse: -; Sonnenschutztyp: Movable; g-Wert: 0,51
2x Gipsfaserplatte | H2 Ebene +2 | WA-LB | 1205Wa 0000002623 | yes |  | m² | Trockenbauarbeiten | Wand | 2x Gipsfaserplatte | WA-LB |  |  | 7.5 | 1205HWa0000002407 | NEW | no | yes | 0 | 0.9 |  | - | AllplanAttributes - ash D_Detailverweis: <undefiniert>; Sicherheitsklasse: -; Sonnenschutztyp: Movable; g-Wert: 0,51
Holzständer + Zwischendämmung | H2 Ebene +2 | WA-HD | 1205Wa 0000002619 | yes |  | m³ | Zimmer- und Holzbauarbeiten | Wand | Holzständer + Zwischendämmung | WA-HD |  |  | 7.5 | 1205HWa0000002407 | NEW | no | yes | 0 | 0.9 |  | - | AllplanAttributes - ash D_Detailverweis: DT D; ash D_Plannummer: D1851; Sicherheitsklasse: -; Sonnenschutztyp: Movable; g-Wert: 0,51; ash W_laufende Nr. Statik: 5 (W 4.0)
Staffel + Zwischendämmung | H2 Ebene +2 | WA-DL | 1205Wa 0000002614 | yes |  | m³ | Zimmer- und Holzbauarbeiten | Wand | Staffel + Zwischendämmung | WA-DL |  |  | 7.5 | 1205HWa0000002407 | NEW | no | yes | 0 | 0.9 |  | - | AllplanAttributes - ash D_Detailverweis: <undefiniert>; Sicherheitsklasse: -; Sonnenschutztyp: Movable; g-Wert: 0,51
 | H2 Ebene +2 | WA-LB | 1205Wa 0000002609 | yes | Codetext | m² | Trockenbauarbeiten | Wand | Außenwand 7-Schalig | WA-LB | 0 | A | 7.5 | 1205HWa0000002407 | NEW | no | yes | 0 | 0.9 | no | - | no | Codetext | AllplanAttributes - ash D_Detailverweis: <undefiniert>; Sicherheitsklasse: -; Sonnenschutztyp: Movable; g-Wert: 0,51
Konterlattung | H2 Ebene +2 | WA-KL | 1205Wa 0000002605 | yes |  | m² | Zimmer- und Holzbauarbeiten | Wand | Konterlattung | WA-KL |  |  | 7.5 | 1205HWa0000002407 | NEW | no | yes | 0 | 0.9 |  | - | AllplanAttributes - ash D_Detailverweis: <undefiniert>; Sicherheitsklasse: -; Sonnenschutztyp: Movable; g-Wert: 0,51
Traglattung | H2 Ebene +2 | WA-TL | 1205Wa 0000002601 | yes |  | m² | Zimmer- und Holzbauarbeiten | Wand | Traglattung | WA-TL |  |  | 7.5 | 1205HWa0000002407 | NEW | no | yes | 0 | 0.9 |  | 32 | AllplanAttributes - ash D_Detailverweis: <undefiniert>; Sicherheitsklasse: -; Sonnenschutztyp: Movable; g-Wert: 0,51
Holzschindel | H2 Ebene +2 | WA-HS | 1205Wa 0000002680 | yes |  | m² | Zimmer- und Holzbauarbeiten | Wand | Holzschindel | WA-HS |  |  | 7.5 | 1205HWa0000002407 | NEW | no | yes | 0 | 0.9 |  | 32 | AllplanAttributes - ash D_Detailverweis: <undefiniert>; Sicherheitsklasse: -; Sonnenschutztyp: Movable; g-Wert: 0,51
2x Gipsfaserplatte | H2 Ebene +2 | WA-LB | 1205Wa 0000178541 | yes |  | m² | Trockenbauarbeiten | Wand | 2x Gipsfaserplatte | WA-LB |  |  | 7.5 | 1205HWa0000178477 | NEW | no | yes | 0 | 0.9 |  | 32 | AllplanAttributes - ash D_Detailverweis: <undefiniert>; Sicherheitsklasse: -; Sonnenschutztyp: Movable; g-Wert: 0,51
2x Gipsfaserplatte | H2 Ebene +2 | WA-LB | 1205Wa 0000178540 | yes |  | m² | Trockenbauarbeiten | Wand | 2x Gipsfaserplatte | WA-LB |  |  | 7.5 | 1205HWa0000178477 | NEW | no | yes | 0 | 0.9 |  | 32 | AllplanAttributes - ash D_Detailverweis: <undefiniert>; Sicherheitsklasse: -; Sonnenschutztyp: Movable; g-Wert: 0,51
Holzständer + Zwischendämmung | H2 Ebene +2 | WA-HD | 1205Wa 0000178539 | yes |  | m³ | Zimmer- und Holzbauarbeiten | Wand | Holzständer + Zwischendämmung | WA-HD |  |  | 7.5 | 1205HWa0000178477 | NEW | no | yes | 0 | 0.9 |  | 32 | AllplanAttributes - ash D_Detailverweis: DT F; ash D_Plannummer: D1851; Sicherheitsklasse: -; Sonnenschutztyp: Movable; g-Wert: 0,51; ash W_laufende Nr. Statik: 6 (W 6.0)
 | H2 Ebene +2 | WA-LB | 1205Wa 0000178538 | yes | Codetext | m² | Trockenbauarbeiten | Wand | Außenwand 7-Schalig | WA-LB | 0 | A | 7.5 | 1205HWa0000178477 | NEW | no | yes | 0 | 0.9 | no | 32 | no | Codetext | AllplanAttributes - ash D_Detailverweis: <undefiniert>; Sicherheitsklasse: -; Sonnenschutztyp: Movable; g-Wert: 0,51
 | H2 Ebene +2 | WA-LB | 1205Wa 0000178537 | yes | Codetext | m² | Trockenbauarbeiten | Wand | Außenwand 7-Schalig | WA-LB | 0 | A | 7.5 | 1205HWa0000178477 | NEW | no | yes | 0 | 0.9 | no | 32 | no | Codetext | AllplanAttributes - ash D_Detailverweis: <undefiniert>; Sicherheitsklasse: -; Sonnenschutztyp: Movable; g-Wert: 0,51
Staffel + Zwischendämmung | H2 Ebene +2 | WA-DL | 1205Wa 0000178536 | yes |  | m³ | Zimmer- und Holzbauarbeiten | Wand | Staffel + Zwischendämmung | WA-DL |  |  | 7.5 | 1205HWa0000178477 | NEW | no | yes | 0 | 0.9 |  | 32 | AllplanAttributes - ash D_Detailverweis: <undefiniert>; Sicherheitsklasse: -; Sonnenschutztyp: Movable; g-Wert: 0,51
Konterlattung | H2 Ebene +2 | WA-KL | 1205Wa 0000178535 | yes |  | m² | Zimmer- und Holzbauarbeiten | Wand | Konterlattung | WA-KL |  |  | 7.5 | 1205HWa0000178477 | NEW | no | yes | 0 | 0.9 |  | 32 | AllplanAttributes - ash D_Detailverweis: <undefiniert>; Sicherheitsklasse: -; Sonnenschutztyp: Movable; g-Wert: 0,51
Traglattung | H2 Ebene +2 | WA-TL | 1205Wa 0000178534 | yes |  | m² | Zimmer- und Holzbauarbeiten | Wand | Traglattung | WA-TL |  |  | 7.5 | 1205HWa0000178477 | NEW | no | yes | 0 | 0.9 |  | 32 | AllplanAttributes - ash D_Detailverweis: <undefiniert>; Sicherheitsklasse: -; Sonnenschutztyp: Movable; g-Wert: 0,51
Holzschindel | H2 Ebene +2 | WA-HS | 1205Wa 0000178533 | yes |  | m² | Zimmer- und Holzbauarbeiten | Wand | Holzschindel | WA-HS |  |  | 7.5 | 1205HWa0000178477 | NEW | no | yes | 0 | 0.9 |  | 32 | AllplanAttributes - ash D_Detailverweis: FS12; ash D_Plannummer: D1854; Sicherheitsklasse: -; Sonnenschutztyp: Movable; g-Wert: 0,51
 | H2 Ebene +2 | WA-LB | 1205Wa 0000001846 | yes | Codetext | m² | Trockenbauarbeiten | Wand | Außenwand 7-Schalig | WA-LB | 0 | A | 7.5 | 1205HWa0000001732 | NEW | no | yes | 0 | 0.9 | no | 32 | no | Codetext | AllplanAttributes - ash D_Detailverweis: <undefiniert>; Sicherheitsklasse: -; Sonnenschutztyp: Movable; g-Wert: 0,51
 | H2 Ebene +2 | WA-HD | 1205Wa 0000001844 | yes | Codetext | m³ | Zimmer- und Holzbauarbeiten | Wand | Außenwand 7-Schalig | WA-HD | 0 | A | 7.5 | 1205HWa0000001732 | NEW | no | yes | 0 | 0.9 | no | 32 | no | Codetext | AllplanAttributes - ash D_Detailverweis: DT C; ash D_Plannummer: D1851; Sicherheitsklasse: -; Sonnenschutztyp: Movable; g-Wert: 0,51; ash W_laufende Nr. Statik: 5 (W 4.0)
 | H2 Ebene +2 | WA-DL | 1205Wa 0000001842 | yes | Codetext | m³ | Zimmer- und Holzbauarbeiten | Wand | Außenwand 7-Schalig | WA-DL | 0 | A | 7.5 | 1205HWa0000001732 | NEW | no | yes | 0 | 0.9 | no | 32 | no | Codetext | AllplanAttributes - ash D_Detailverweis: <undefiniert>; Sicherheitsklasse: -; Sonnenschutztyp: Movable; g-Wert: 0,51
 | H2 Ebene +2 | WA-LB | 1205Wa 0000001840 | yes | Codetext | m² | Trockenbauarbeiten | Wand | Außenwand 7-Schalig | WA-LB | 0 | A | 7.5 | 1205HWa0000001732 | NEW | no | yes | 0 | 0.9 | no | 32 | no | Codetext | AllplanAttributes - ash D_Detailverweis: <undefiniert>; Sicherheitsklasse: -; Sonnenschutztyp: Movable; g-Wert: 0,51
 | H2 Ebene +2 | WA-KL | 1205Wa 0000001838 | yes | Codetext | m² | Zimmer- und Holzbauarbeiten | Wand | Außenwand 7-Schalig | WA-KL | 0 | A | 7.5 | 1205HWa0000001732 | NEW | no | yes | 0 | 0.9 | no | 32 | no | Codetext | AllplanAttributes - ash D_Detailverweis: <undefiniert>; Sicherheitsklasse: -; Sonnenschutztyp: Movable; g-Wert: 0,51
 | H2 Ebene +2 | WA-TL | 1205Wa 0000001836 | yes | Codetext | m² | Zimmer- und Holzbauarbeiten | Wand | Außenwand 7-Schalig | WA-TL | 0 | A | 7.5 | 1205HWa0000001732 | NEW | no | yes | 0 | 0.9 | no | 32 | no | Codetext | AllplanAttributes - ash D_Detailverweis: <undefiniert>; Sicherheitsklasse: -; Sonnenschutztyp: Movable; g-Wert: 0,51
 | H2 Ebene +2 | WA-HS | 1205Wa 0000001834 | yes | Codetext | m² | Zimmer- und Holzbauarbeiten | Wand | Außenwand 7-Schalig | WA-HS | 0 | A | 7.5 | 1205HWa0000001732 | NEW | no | yes | 0 | 0.9 | no | 32 | no | Codetext | AllplanAttributes - ash D_Detailverweis: <undefiniert>; Sicherheitsklasse: -; Sonnenschutztyp: Movable; g-Wert: 0,51
2x Gipsfaserplatte | H2 Ebene +2 | WA-LB | 1205Wa 0000180501 | yes |  | m² | Trockenbauarbeiten | Wand | 2x Gipsfaserplatte | WA-LB |  |  | 7.5 | 1205HWa0000180491 | NEW | no | yes | REI-M 60-D,s2,d0 + A1 | AllplanAttributes - Ortscode_Geschoßbezeichnung: E00; ash D_Detailverweis: <undefiniert>; Sicherheitsklasse: -
Holzwerkstoffplatte | H2 Ebene +2 | WA-LB | 1205Wa 0000180500 | yes |  | m³ | Trockenbauarbeiten | Wand | Holzwerkstoffplatte | WA-LB |  |  | 7.5 | 1205HWa0000180491 | NEW | yes | yes | REI-M 60-D,s2,d0 + A1 | AllplanAttributes - Ortscode_Geschoßbezeichnung: E00; ash D_Detailverweis: <undefiniert>; Sicherheitsklasse: -
Holzständer + Zwischendämmung | H2 Ebene +2 | WA-HD | 1205Wa 0000180499 | yes |  | m³ | Zimmer- und Holzbauarbeiten | Wand | Holzständer + Zwischendämmung | WA-HD |  |  | 7.5 | 1205HWa0000180491 | NEW | yes | yes | REI-M 60-D,s2,d0 + A1 | AllplanAttributes - Ortscode_Geschoßbezeichnung: E00; ash D_Detailverweis: DT A; ash D_Plannummer: D1850; Sicherheitsklasse: -; ash W_laufende Nr. Statik: 6 (W 6.0)
Holzwerkstoffplatte | H2 Ebene +2 | WA-LB | 1205Wa 0000180498 | yes |  | m³ | Trockenbauarbeiten | Wand | Holzwerkstoffplatte | WA-LB |  |  | 7.5 | 1205HWa0000180491 | NEW | yes | yes | REI-M 60-D,s2,d0 + A1 | AllplanAttributes - Ortscode_Geschoßbezeichnung: E00; ash D_Detailverweis: <undefiniert>; Sicherheitsklasse: -
nichtbrennbare Trägerplatte | H2 Ebene +2 | WA-TP | 1205Wa 0000180497 | yes |  | m² | Trockenbauarbeiten | Wand | nichtbrennbare Trägerplatte | WA-TP |  |  | 7.5 | 1205HWa0000180491 | NEW | no | yes | REI-M 60-D,s2,d0 + A1 | AllplanAttributes - Ortscode_Geschoßbezeichnung: E00; ash D_Detailverweis: <undefiniert>; Sicherheitsklasse: -
Staffel + Zwischendämmung | H2 Ebene +2 | WA-DL | 1205Wa 0000180496 | yes |  | m³ | Zimmer- und Holzbauarbeiten | Wand | Staffel + Zwischendämmung | WA-DL |  |  | 7.5 | 1205HWa0000180491 | NEW | no | yes | REI-M 60-D,s2,d0 + A1 | AllplanAttributes - Ortscode_Geschoßbezeichnung: E00; ash D_Detailverweis: <undefiniert>; Sicherheitsklasse: -
Konterlattung | H2 Ebene +2 | WA-KL | 1205Wa 0000180495 | yes |  | m² | Zimmer- und Holzbauarbeiten | Wand | Konterlattung | WA-KL |  |  | 7.5 | 1205HWa0000180491 | NEW | no | yes | REI-M 60-D,s2,d0 + A1 | AllplanAttributes - Ortscode_Geschoßbezeichnung: E00; ash D_Detailverweis: <undefiniert>; Sicherheitsklasse: -
Traglattung | H2 Ebene +2 | WA-TL | 1205Wa 0000180494 | yes |  | m² | Zimmer- und Holzbauarbeiten | Wand | Traglattung | WA-TL |  |  | 7.5 | 1205HWa0000180491 | NEW | no | yes | REI-M 60-D,s2,d0 + A1 | AllplanAttributes - Ortscode_Geschoßbezeichnung: E00; ash D_Detailverweis: <undefiniert>; Sicherheitsklasse: -
Holzschindel | H2 Ebene +2 | WA-HS | 1205Wa 0000180493 | yes |  | m² | Zimmer- und Holzbauarbeiten | Wand | Holzschindel | WA-HS |  |  | 7.5 | 1205HWa0000180491 | NEW | no | yes | REI-M 60-D,s2,d0 + A1 | AllplanAttributes - Ortscode_Geschoßbezeichnung: E00; ash D_Detailverweis: <undefiniert>; Sicherheitsklasse: -
 | H2 Ebene +2 | WA-LB | 1205Wa 0000002821 | yes | Codetext | m² | Trockenbauarbeiten | Wand | Außenwand 7-Schalig | WA-LB | 0 | A | 7.5 | 1205HWa0000002753 | NEW | no | yes | 0 | 0.9 | no | 32 | no | Codetext | AllplanAttributes - ash D_Detailverweis: <undefiniert>; Sicherheitsklasse: -; Sonnenschutztyp: Movable; g-Wert: 0,51
 | H2 Ebene +2 | WA-HD | 1205Wa 0000002819 | yes | Codetext | m³ | Zimmer- und Holzbauarbeiten | Wand | Außenwand 7-Schalig | WA-HD | 0 | A | 7.5 | 1205HWa0000002753 | NEW | no | yes | 0 | 0.9 | no | 32 | no | Codetext | AllplanAttributes - ash D_Detailverweis: DT B; ash D_Plannummer: D1851; Sicherheitsklasse: -; Sonnenschutztyp: Movable; g-Wert: 0,51; ash W_laufende Nr. Statik: 5 (W 4.0)
 | H2 Ebene +2 | WA-DL | 1205Wa 0000002817 | yes | Codetext | m³ | Zimmer- und Holzbauarbeiten | Wand | Außenwand 7-Schalig | WA-DL | 0 | A | 7.5 | 1205HWa0000002753 | NEW | no | yes | 0 | 0.9 | no | 32 | no | Codetext | AllplanAttributes - ash D_Detailverweis: <undefiniert>; Sicherheitsklasse: -; Sonnenschutztyp: Movable; g-Wert: 0,51
 | H2 Ebene +2 | WA-LB | 1205Wa 0000002815 | yes | Codetext | m² | Trockenbauarbeiten | Wand | Außenwand 7-Schalig | WA-LB | 0 | A | 7.5 | 1205HWa0000002753 | NEW | no | yes | 0 | 0.9 | no | 32 | no | Codetext | AllplanAttributes - ash D_Detailverweis: <undefiniert>; Sicherheitsklasse: -; Sonnenschutztyp: Movable; g-Wert: 0,51
 | H2 Ebene +2 | WA-KL | 1205Wa 0000002813 | yes | Codetext | m² | Zimmer- und Holzbauarbeiten | Wand | Außenwand 7-Schalig | WA-KL | 0 | A | 7.5 | 1205HWa0000002753 | NEW | no | yes | 0 | 0.9 | no | 32 | no | Codetext | AllplanAttributes - ash D_Detailverweis: <undefiniert>; Sicherheitsklasse: -; Sonnenschutztyp: Movable; g-Wert: 0,51
 | H2 Ebene +2 | WA-TL | 1205Wa 0000002811 | yes | Codetext | m² | Zimmer- und Holzbauarbeiten | Wand | Außenwand 7-Schalig | WA-TL | 0 | A | 7.5 | 1205HWa0000002753 | NEW | no | yes | 0 | 0.9 | no | 32 | no | Codetext | AllplanAttributes - ash D_Detailverweis: <undefiniert>; Sicherheitsklasse: -; Sonnenschutztyp: Movable; g-Wert: 0,51
 | H2 Ebene +2 | WA-HS | 1205Wa 0000002809 | yes | Codetext | m² | Zimmer- und Holzbauarbeiten | Wand | Außenwand 7-Schalig | WA-HS | 0 | A | 7.5 | 1205HWa0000002753 | NEW | no | yes | 0 | 0.9 | no | 32 | no | Codetext | AllplanAttributes - ash D_Detailverweis: <undefiniert>; Sicherheitsklasse: -; Sonnenschutztyp: Movable; g-Wert: 0,51
 | H2 Ebene +2 | WA-LB | 1205Wa 0000001093 | yes | Codetext | m² | Trockenbauarbeiten | Wand | Außenwand 7-Schalig | WA-LB | 0 | A | 7.5 | 1205HWa0000000994 | NEW | no | yes | 0 | 0.9 | no | 35 | no | Codetext | AllplanAttributes - ash D_Detailverweis: <undefiniert>; Sicherheitsklasse: -; Sonnenschutztyp: Movable; g-Wert: 0,51
 | H2 Ebene +2 | WA-HD | 1205Wa 0000001097 | yes | Codetext | m³ | Zimmer- und Holzbauarbeiten | Wand | Außenwand 7-Schalig | WA-HD | 0 | A | 7.5 | 1205HWa0000000994 | NEW | no | yes | 0 | 0.9 | no | 35 | no | Codetext | AllplanAttributes - ash D_Detailverweis: <undefiniert>; Sicherheitsklasse: -; Sonnenschutztyp: Movable; g-Wert: 0,51; ash W_laufende Nr. Statik: 2 (W 2.0/ 2.1/ 2.2)
 | H2 Ebene +2 | WA-DL | 1205Wa 0000001117 | yes | Codetext | m³ | Zimmer- und Holzbauarbeiten | Wand | Außenwand 7-Schalig | WA-DL | 0 | A | 7.5 | 1205HWa0000000994 | NEW | no | yes | 0 | 0.9 | no | 35 | no | Codetext | AllplanAttributes - ash D_Detailverweis: <undefiniert>; Sicherheitsklasse: -; Sonnenschutztyp: Movable; g-Wert: 0,51
 | H2 Ebene +2 | WA-LB | 1205Wa 0000001113 | yes | Codetext | m² | Trockenbauarbeiten | Wand | Außenwand 7-Schalig | WA-LB | 0 | A | 7.5 | 1205HWa0000000994 | NEW | no | yes | 0 | 0.9 | no | 35 | no | Codetext | AllplanAttributes - ash D_Detailverweis: <undefiniert>; Sicherheitsklasse: -; Sonnenschutztyp: Movable; g-Wert: 0,51
 | H2 Ebene +2 | WA-KL | 1205Wa 0000001109 | yes | Codetext | m² | Zimmer- und Holzbauarbeiten | Wand | Außenwand 7-Schalig | WA-KL | 0 | A | 7.5 | 1205HWa0000000994 | NEW | no | yes | 0 | 0.9 | no | 35 | no | Codetext | AllplanAttributes - ash D_Detailverweis: <undefiniert>; Sicherheitsklasse: -; Sonnenschutztyp: Movable; g-Wert: 0,51
 | H2 Ebene +2 | WA-TL | 1205Wa 0000001105 | yes | Codetext | m² | Zimmer- und Holzbauarbeiten | Wand | Außenwand 7-Schalig | WA-TL | 0 | A | 7.5 | 1205HWa0000000994 | NEW | no | yes | 0 | 0.9 | no | 35 | no | Codetext | AllplanAttributes - ash D_Detailverweis: <undefiniert>; Sicherheitsklasse: -; Sonnenschutztyp: Movable; g-Wert: 0,51
 | H2 Ebene +2 | WA-HS | 1205Wa 0000001101 | yes | Codetext | m² | Zimmer- und Holzbauarbeiten | Wand | Außenwand 7-Schalig | WA-HS | 0 | A | 7.5 | 1205HWa0000000994 | NEW | no | yes | 0 | 0.9 | no | 35 | no | Codetext | AllplanAttributes - ash D_Detailverweis: FS 2; ash D_Plannummer: D781; Sicherheitsklasse: -; Sonnenschutztyp: Movable; g-Wert: 0,51
 | H2 Ebene +2 | WA-FAS | 1205Wa 0000327512 | yes | Codetext | m² | Vorgehängte Fassaden | Wand | Außenwand mehrschalig | WA-FAS | 0 | A |  | 1106HWa0000000475 | NEW | no | yes | 0 | 0 | no | 0 | no | Codetext
 | H2 Ebene +2 | WA-FAS | 1205Wa 0000327508 | yes | Codetext | m² | Vorgehängte Fassaden | Wand | Außenwand mehrschalig | WA-FAS | 0 | A |  | 1106HWa0000000475 | NEW | no | yes | 0 | 0 | no | 0 | no | Codetext
 | H2 Ebene +2 | WI-SYS | 1205Wa 0000327504 | yes | Codetext | m² | Trockenbauarbeiten | Wand | Außenwand mehrschalig | WI-SYS | 0 | A |  |  | NEW | no | yes | 0 | 0 | no | 0 | no | Codetext
 | H2 Ebene +2 | WI-SYS | 1205Wa 0000327500 | yes | Codetext | m² | Trockenbauarbeiten | Wand | Außenwand mehrschalig | WI-SYS | 0 | A |  |  | NEW | no | yes | 0 | 0 | no | 0 | no | Codetext
 | H2 Ebene +2 | WA-FAS | 1205Wa 0000327496 | yes | Codetext | m² | Vorgehängte Fassaden | Wand | Außenwand mehrschalig | WA-FAS | 0 | A |  | 1106HWa0000000475 | NEW | no | yes | 0 | 0 | no | 0 | no | Codetext
 | H2 Ebene +2 | WA-FAS | 1205Wa 0000327492 | yes | Codetext | m² | Vorgehängte Fassaden | Wand | Außenwand mehrschalig | WA-FAS | 0 | A |  | 1106HWa0000000475 | NEW | no | yes | 0 | 0 | no | 0 | no | Codetext
 | H2 Ebene +2 | WA-FAS | 1205Wa 0000329745 | yes | Codetext | m² | Vorgehängte Fassaden | Wand | Außenwand mehrschalig | WA-FAS | 0 | A |  | 1106HWa0000000475 | NEW | no | yes | 0 | 0 | no | 0 | no | Codetext
 | H2 Ebene +2 | WA-FAS | 1205Wa 0000329746 | yes | Codetext | m² | Vorgehängte Fassaden | Wand | Außenwand mehrschalig | WA-FAS | 0 | A |  | 1106HWa0000000475 | NEW | no | yes | 0 | 0 | no | 0 | no | Codetext
 | H2 Ebene +2 | WA-FAS | 1205Wa 0000332084 | yes | Codetext | m² | Vorgehängte Fassaden | Wand | Außenwand mehrschalig | WA-FAS | 0 | A |  | 1106HWa0000000475 | NEW | no | yes | 0 | 0 | no | 0 | no | Codetext
 | H2 Ebene +2 | WA-FAS | 1205Wa 0000332085 | yes | Codetext | m² | Vorgehängte Fassaden | Wand | Außenwand mehrschalig | WA-FAS | 0 | A |  | 1106HWa0000000475 | NEW | no | yes | 0 | 0 | no | 0 | no | Codetext
 | H2 Ebene +2 | WI-SYS | 1205Wa 0000332086 | yes | Codetext | m² | Trockenbauarbeiten | Wand | Außenwand mehrschalig | WI-SYS | 0 | A |  |  | NEW | no | yes | 0 | 0 | no | 0 | no | Codetext
 | H2 Ebene +2 | WI-SYS | 1205Wa 0000332070 | yes | Codetext | m² | Trockenbauarbeiten | Wand | Außenwand mehrschalig | WI-SYS | 0 | A |  |  | NEW | no | yes | 0 | 0 | no | 0 | no | Codetext
 | H2 Ebene +2 | WA-FAS | 1205Wa 0000332071 | yes | Codetext | m² | Vorgehängte Fassaden | Wand | Außenwand mehrschalig | WA-FAS | 0 | A |  | 1106HWa0000000475 | NEW | no | yes | 0 | 0 | no | 0 | no | Codetext
 | H2 Ebene +2 | WA-FAS | 1205Wa 0000332072 | yes | Codetext | m² | Vorgehängte Fassaden | Wand | Außenwand mehrschalig | WA-FAS | 0 | A |  | 1106HWa0000000475 | NEW | no | yes | 0 | 0 | no | 0 | no | Codetext
 | H2 Ebene +2 | WA-FAS | 1205Wa 0000332083 | yes | Codetext | m² | Vorgehängte Fassaden | Wand | Außenwand mehrschalig | WA-FAS | 0 | A |  | 1106HWa0000000475 | NEW | no | yes | 0 | 0 | no | 0 | no | Codetext
 | H2 Ebene +2 | WA-FAS | 1205Wa 0000332082 | yes | Codetext | m² | Vorgehängte Fassaden | Wand | Außenwand mehrschalig | WA-FAS | 0 | A |  | 1106HWa0000000475 | NEW | no | yes | 0 | 0 | no | 0 | no | Codetext
 | H2 Ebene +2 | WA-LB | 1205Wa 0000102227 | yes | Codetext | m² | Trockenbauarbeiten | Wand | Außenwand 7-Schalig | WA-LB | 0 | A | 7.5 | 1205HWa0000101942 | NEW | no | yes | 0 | 0.9 | no | 32 | no | Codetext | AllplanAttributes - ash D_Detailverweis: <undefiniert>; Sicherheitsklasse: -; Sonnenschutztyp: Movable; g-Wert: 0,51
 | H2 Ebene +2 | WA-HD | 1205Wa 0000102231 | yes | Codetext | m³ | Zimmer- und Holzbauarbeiten | Wand | Außenwand 7-Schalig | WA-HD | 0 | A | 7.5 | 1205HWa0000101942 | NEW | no | yes | 0 | 0.9 | no | 32 | no | Codetext | AllplanAttributes - ash D_Detailverweis: <undefiniert>; Sicherheitsklasse: -; Sonnenschutztyp: Movable; g-Wert: 0,51
 | H2 Ebene +2 | WA-DL | 1205Wa 0000102235 | yes | Codetext | m³ | Zimmer- und Holzbauarbeiten | Wand | Außenwand 7-Schalig | WA-DL | 0 | A | 7.5 | 1205HWa0000101942 | NEW | no | yes | 0 | 0.9 | no | 32 | no | Codetext | AllplanAttributes - ash D_Detailverweis: <undefiniert>; Sicherheitsklasse: -; Sonnenschutztyp: Movable; g-Wert: 0,51
 | H2 Ebene +2 | WA-LB | 1205Wa 0000102239 | yes | Codetext | m² | Trockenbauarbeiten | Wand | Außenwand 7-Schalig | WA-LB | 0 | A | 7.5 | 1205HWa0000101942 | NEW | no | yes | 0 | 0.9 | no | 32 | no | Codetext | AllplanAttributes - ash D_Detailverweis: <undefiniert>; Sicherheitsklasse: -; Sonnenschutztyp: Movable; g-Wert: 0,51
 | H2 Ebene +2 | WA-KL | 1205Wa 0000102243 | yes | Codetext | m² | Zimmer- und Holzbauarbeiten | Wand | Außenwand 7-Schalig | WA-KL | 0 | A | 7.5 | 1205HWa0000101942 | NEW | no | yes | 0 | 0.9 | no | 32 | no | Codetext | AllplanAttributes - ash D_Detailverweis: <undefiniert>; Sicherheitsklasse: -; Sonnenschutztyp: Movable; g-Wert: 0,51
 | H2 Ebene +2 | WA-TL | 1205Wa 0000102247 | yes | Codetext | m² | Zimmer- und Holzbauarbeiten | Wand | Außenwand 7-Schalig | WA-TL | 0 | A | 7.5 | 1205HWa0000101942 | NEW | no | yes | 0 | 0.9 | no | 32 | no | Codetext | AllplanAttributes - ash D_Detailverweis: <undefiniert>; Sicherheitsklasse: -; Sonnenschutztyp: Movable; g-Wert: 0,51
 | H2 Ebene +2 | WA-HS | 1205Wa 0000102251 | yes | Codetext | m² | Zimmer- und Holzbauarbeiten | Wand | Außenwand 7-Schalig | WA-HS | 0 | A | 7.5 | 1205HWa0000101942 | NEW | no | yes | 0 | 0.9 | no | 32 | no | Codetext | AllplanAttributes - ash D_Detailverweis: <undefiniert>; Sicherheitsklasse: -; Sonnenschutztyp: Movable; g-Wert: 0,51
Holzständer + Zwischendämmung | H2 Ebene +2 | WA-HD | 1205Wa 0000252471 | yes |  | m³ | Zimmer- und Holzbauarbeiten | Wand | Holzständer + Zwischendämmung | WA-HD |  |  | 7.5 | 1205HWa0000119458 | NEW | no | yes | 0 | 0.9 |  | 32 | AllplanAttributes - Ortscode_Geschoßbezeichnung: E02; ash D_Detailverweis: <undefiniert>; Sicherheitsklasse: -; Sonnenschutztyp: Movable; g-Wert: 0,51
Staffel + Zwischendämmung | H2 Ebene +2 | WA-DL | 1205Wa 0000252466 | yes |  | m³ | Zimmer- und Holzbauarbeiten | Wand | Staffel + Zwischendämmung | WA-DL |  |  | 7.5 | 1205HWa0000119497 | NEW | no | yes | 0 | 0.9 |  | 32 | AllplanAttributes - ash D_Detailverweis: <undefiniert>; Sicherheitsklasse: -; Sonnenschutztyp: Movable; g-Wert: 0,51
 | H2 Ebene +2 | WA-LB | 1205Wa 0000252469 | yes | Codetext | m² | Trockenbauarbeiten | Wand | Außenwand 7-Schalig | WA-LB | 0 | A | 7.5 | 1205HWa0000119497 | NEW | no | yes | 0 | 0.9 | no | 32 | no | Codetext | AllplanAttributes - ash D_Detailverweis: <undefiniert>; Sicherheitsklasse: -; Sonnenschutztyp: Movable; g-Wert: 0,51
Konterlattung | H2 Ebene +2 | WA-KL | 1205Wa 0000252468 | yes |  | m² | Zimmer- und Holzbauarbeiten | Wand | Konterlattung | WA-KL |  |  | 7.5 | 1205HWa0000119497 | NEW | no | yes | 0 | 0.9 |  | 32 | AllplanAttributes - ash D_Detailverweis: <undefiniert>; Sicherheitsklasse: -; Sonnenschutztyp: Movable; g-Wert: 0,51
Traglattung | H2 Ebene +2 | WA-TL | 1205Wa 0000252467 | yes |  | m² | Zimmer- und Holzbauarbeiten | Wand | Traglattung | WA-TL |  |  | 7.5 | 1205HWa0000119497 | NEW | no | yes | 0 | 0.9 |  | 32 | AllplanAttributes - ash D_Detailverweis: <undefiniert>; Sicherheitsklasse: -; Sonnenschutztyp: Movable; g-Wert: 0,51
Holzschindel | H2 Ebene +2 | WA-HS | 1205Wa 0000252470 | yes |  | m² | Zimmer- und Holzbauarbeiten | Wand | Holzschindel | WA-HS |  |  | 7.5 | 1205HWa0000119497 | NEW | no | yes | 0 | 0.9 |  | 32 | AllplanAttributes - ash D_Detailverweis: <undefiniert>; Sicherheitsklasse: -; Sonnenschutztyp: Movable; g-Wert: 0,51
 | H2 Ebene +2 | WA-LB | 1205Wa 0000333732 | yes | Codetext | m² | Trockenbauarbeiten | Wand | Außenwand 7-Schalig | WA-LB | 0 | A | 7.5 | 1205HWa0000001726 | NEW | no | yes | 0 | 0.9 | no | 32 | no | Codetext | AllplanAttributes - ash D_Detailverweis: <undefiniert>; Sicherheitsklasse: -; Sonnenschutztyp: Movable; g-Wert: 0,51
 | H2 Ebene +2 | WA-LB | 1205Wa 0000333733 | yes | Codetext | m² | Trockenbauarbeiten | Wand | Außenwand 7-Schalig | WA-LB | 0 | A | 7.5 | 1205HWa0000001726 | NEW | no | yes | 0 | 0.9 | no | 32 | no | Codetext | AllplanAttributes - ash D_Detailverweis: <undefiniert>; Sicherheitsklasse: -; Sonnenschutztyp: Movable; g-Wert: 0,51
 | H2 Ebene +2 | WA-HD | 1205Wa 0000333734 | yes | Codetext | m³ | Zimmer- und Holzbauarbeiten | Wand | Außenwand 7-Schalig | WA-HD | 0 | A | 7.5 | 1205HWa0000001726 | NEW | no | yes | 0 | 0.9 | no | 32 | no | Codetext | AllplanAttributes - ash D_Detailverweis: <undefiniert>; Sicherheitsklasse: -; Sonnenschutztyp: Movable; g-Wert: 0,51; ash W_laufende Nr. Statik: 5 (W 4.0)
 | H2 Ebene +2 | WA-DL | 1205Wa 0000333743 | yes | Codetext | m³ | Zimmer- und Holzbauarbeiten | Wand | Außenwand 7-Schalig | WA-DL | 0 | A | 7.5 | 1205HWa0000001726 | NEW | no | yes | 0 | 0.9 | no | 32 | no | Codetext | AllplanAttributes - ash D_Detailverweis: <undefiniert>; Sicherheitsklasse: -; Sonnenschutztyp: Movable; g-Wert: 0,51
 | H2 Ebene +2 | WA-LB | 1205Wa 0000333731 | yes | Codetext | m² | Trockenbauarbeiten | Wand | Außenwand 7-Schalig | WA-LB | 0 | A | 7.5 | 1205HWa0000001726 | NEW | no | yes | 0 | 0.9 | no | 32 | no | Codetext | AllplanAttributes - ash D_Detailverweis: <undefiniert>; Sicherheitsklasse: -; Sonnenschutztyp: Movable; g-Wert: 0,51
 | H2 Ebene +2 | WA-LB | 1205Wa 0000334812 | yes | Codetext | m² | Trockenbauarbeiten | Wand | Außenwand 7-Schalig | WA-LB | 0 | A | 7.5 | 1205HWa0000180267 | NEW | no | yes | 0 | 0.9 | no | 32 | no | Codetext | AllplanAttributes - ash D_Detailverweis: <undefiniert>; Sicherheitsklasse: -; Sonnenschutztyp: Movable; g-Wert: 0,51
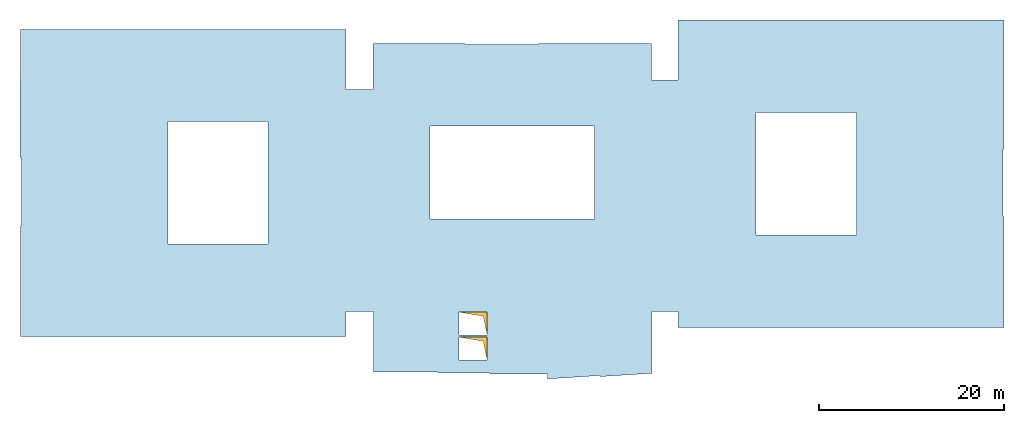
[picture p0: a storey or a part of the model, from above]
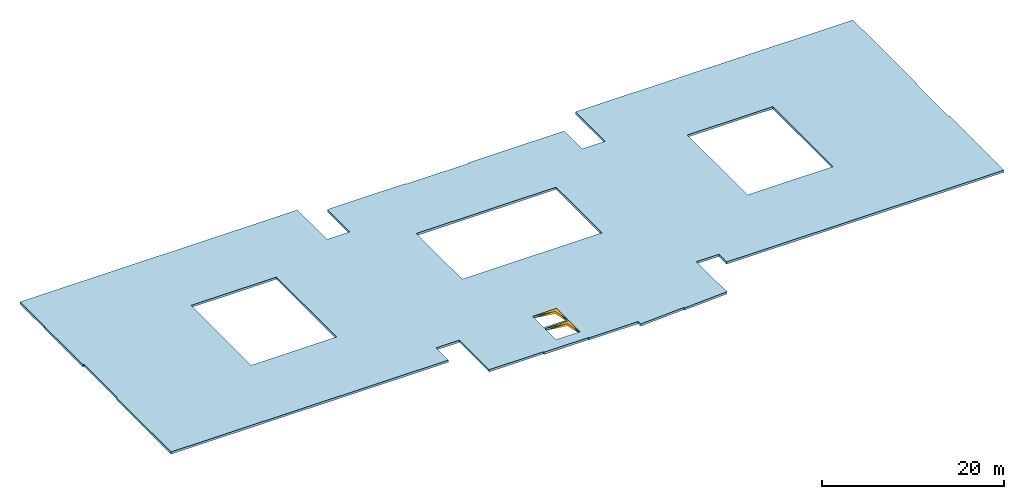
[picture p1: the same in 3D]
Properties of the parts of a building model (IFC4), part 52 of 80

# IfcWall (6826)
Name | In | Material | Allright_Bauteil_ID | 2D Interaktion | Codetext | Abrechnungsart | Gewerk | Objektname | Bezeichnung | AllplanAttributes, Material | Typ = SurfaceSpreadOfFlame | Brandschutzklasse | OKFF | P_ID | Status | LoadBearing | IsExternal | FireRating | ThermalTransmittance (W/K/m2) | Combustible | AcousticRating | Compartmentation | Reference
 | H2 Ebene +2 | WA-HD | 1205Wa 0000334811 | yes | Codetext | m³ | Zimmer- und Holzbauarbeiten | Wand | Außenwand 7-Schalig | WA-HD | 0 | A | 7.5 | 1205HWa0000180267 | NEW | no | yes | 0 | 0.9 | no | 32 | no | Codetext | AllplanAttributes - ash D_Detailverweis: <undefiniert>; Sicherheitsklasse: -; Sonnenschutztyp: Movable; g-Wert: 0,51; ash W_laufende Nr. Statik: 5 (W 4.0)
 | H2 Ebene +2 | WA-DL | 1205Wa 0000334818 | yes | Codetext | m³ | Zimmer- und Holzbauarbeiten | Wand | Außenwand 7-Schalig | WA-DL | 0 | A | 7.5 | 1205HWa0000180267 | NEW | no | yes | 0 | 0.9 | no | 32 | no | Codetext | AllplanAttributes - ash D_Detailverweis: <undefiniert>; Sicherheitsklasse: -; Sonnenschutztyp: Movable; g-Wert: 0,51
 | H2 Ebene +2 | WA-LB | 1205Wa 0000334817 | yes | Codetext | m² | Trockenbauarbeiten | Wand | Außenwand 7-Schalig | WA-LB | 0 | A | 7.5 | 1205HWa0000180267 | NEW | no | yes | 0 | 0.9 | no | 32 | no | Codetext | AllplanAttributes - ash D_Detailverweis: <undefiniert>; Sicherheitsklasse: -; Sonnenschutztyp: Movable; g-Wert: 0,51
 | H2 Ebene +2 | WA-LB | 1205Wa 0000344705 | yes | Codetext | m² | Trockenbauarbeiten | Wand | Außenwand 7-Schalig | WA-LB | 0 | A | 7.5 | 1205HWa0000094929 | NEW | no | yes | 0 | 0.9 | no | - | no | Codetext | AllplanAttributes - ash D_Detailverweis: <undefiniert>; Sicherheitsklasse: -; Sonnenschutztyp: Movable; g-Wert: 0,51
 | H2 Ebene +2 | WA-DL | 1205Wa 0000344706 | yes | Codetext | m³ | Zimmer- und Holzbauarbeiten | Wand | Außenwand 7-Schalig | WA-DL | 0 | A | 7.5 | 1205HWa0000094929 | NEW | no | yes | 0 | 0.9 | no | - | no | Codetext | AllplanAttributes - ash D_Detailverweis: <undefiniert>; Sicherheitsklasse: -; Sonnenschutztyp: Movable; g-Wert: 0,51; ash W_laufende Nr. Statik: 8 (W 10.0)
 | H2 Ebene +2 | WA-DL | 1205Wa 0000344707 | yes | Codetext | m³ | Zimmer- und Holzbauarbeiten | Wand | Außenwand 7-Schalig | WA-DL | 0 | A | 7.5 | 1205HWa0000094929 | NEW | no | yes | 0 | 0.9 | no | - | no | Codetext | AllplanAttributes - ash D_Detailverweis: <undefiniert>; Sicherheitsklasse: -; Sonnenschutztyp: Movable; g-Wert: 0,51
 | H2 Ebene +2 | WA-DL | 1205Wa 0000344708 | yes | Codetext | m³ | Zimmer- und Holzbauarbeiten | Wand | Außenwand 7-Schalig | WA-DL | 0 | A | 7.5 | 1205HWa0000094929 | NEW | no | yes | 0 | 0.9 | no | - | no | Codetext | AllplanAttributes - ash D_Detailverweis: <undefiniert>; Sicherheitsklasse: -; Sonnenschutztyp: Movable; g-Wert: 0,51
 | H2 Ebene +2 | WA-LB | 1205Wa 0000344709 | yes | Codetext | m² | Trockenbauarbeiten | Wand | Außenwand 7-Schalig | WA-LB | 0 | A | 7.5 | 1205HWa0000094929 | NEW | no | yes | 0 | 0.9 | no | - | no | Codetext | AllplanAttributes - ash D_Detailverweis: <undefiniert>; Sicherheitsklasse: -; Sonnenschutztyp: Movable; g-Wert: 0,51
 | H2 Ebene +2 | WA-KL | 1205Wa 0000344710 | yes | Codetext | m² | Zimmer- und Holzbauarbeiten | Wand | Außenwand 7-Schalig | WA-KL | 0 | A | 7.5 | 1205HWa0000094929 | NEW | no | yes | 0 | 0.9 | no | - | no | Codetext | AllplanAttributes - ash D_Detailverweis: <undefiniert>; Sicherheitsklasse: -; Sonnenschutztyp: Movable; g-Wert: 0,51
 | H2 Ebene +2 | WA-TL | 1205Wa 0000344711 | yes | Codetext | m² | Zimmer- und Holzbauarbeiten | Wand | Außenwand 7-Schalig | WA-TL | 0 | A | 7.5 | 1205HWa0000094929 | NEW | no | yes | 0 | 0.9 | no | - | no | Codetext | AllplanAttributes - ash D_Detailverweis: <undefiniert>; Sicherheitsklasse: -; Sonnenschutztyp: Movable; g-Wert: 0,51
 | H2 Ebene +2 | WA-HS | 1205Wa 0000344712 | yes | Codetext | m² | Zimmer- und Holzbauarbeiten | Wand | Außenwand 7-Schalig | WA-HS | 0 | A | 7.5 | 1205HWa0000094929 | NEW | no | yes | 0 | 0.9 | no | - | no | Codetext | AllplanAttributes - ash D_Detailverweis: <undefiniert>; Sicherheitsklasse: -; Sonnenschutztyp: Movable; g-Wert: 0,51
 | H2 Ebene +2 | WA-LB | 1205Wa 0000354170 | yes | Codetext | m² | Trockenbauarbeiten | Wand | Außenwand 7-Schalig | WA-LB | 0 | A | 7.5 | 1205HWa0000003206 | NEW | no | yes | 0 | 0.9 | no | - | no | Codetext | AllplanAttributes - ash D_Detailverweis: <undefiniert>; Sicherheitsklasse: -; Sonnenschutztyp: Movable; g-Wert: 0,51
 | H2 Ebene +2 | WA-DL | 1205Wa 0000354171 | yes | Codetext | m³ | Zimmer- und Holzbauarbeiten | Wand | Außenwand 7-Schalig | WA-DL | 0 | A | 7.5 | 1205HWa0000003206 | NEW | no | yes | 0 | 0.9 | no | - | no | Codetext | AllplanAttributes - ash D_Detailverweis: DT D; ash D_Plannummer: D1851; Sicherheitsklasse: -; Sonnenschutztyp: Movable; g-Wert: 0,51; ash W_laufende Nr. Statik: 2 (W 2.0/ 2.1/ 2.2)
 | H2 Ebene +2 | WA-DL | 1205Wa 0000354172 | yes | Codetext | m³ | Zimmer- und Holzbauarbeiten | Wand | Außenwand 7-Schalig | WA-DL | 0 | A | 7.5 | 1205HWa0000003206 | NEW | no | yes | 0 | 0.9 | no | - | no | Codetext | AllplanAttributes - ash D_Detailverweis: <undefiniert>; Sicherheitsklasse: -; Sonnenschutztyp: Movable; g-Wert: 0,51
 | H2 Ebene +2 | WA-LB | 1205Wa 0000354173 | yes | Codetext | m² | Trockenbauarbeiten | Wand | Außenwand 7-Schalig | WA-LB | 0 | A | 7.5 | 1205HWa0000003206 | NEW | no | yes | 0 | 0.9 | no | - | no | Codetext | AllplanAttributes - ash D_Detailverweis: <undefiniert>; Sicherheitsklasse: -; Sonnenschutztyp: Movable; g-Wert: 0,51
 | H2 Ebene +2 | WA-KL | 1205Wa 0000354174 | yes | Codetext | m² | Zimmer- und Holzbauarbeiten | Wand | Außenwand 7-Schalig | WA-KL | 0 | A | 7.5 | 1205HWa0000003206 | NEW | no | yes | 0 | 0.9 | no | - | no | Codetext | AllplanAttributes - ash D_Detailverweis: <undefiniert>; Sicherheitsklasse: -; Sonnenschutztyp: Movable; g-Wert: 0,51
 | H2 Ebene +2 | WA-TL | 1205Wa 0000354175 | yes | Codetext | m² | Zimmer- und Holzbauarbeiten | Wand | Außenwand 7-Schalig | WA-TL | 0 | A | 7.5 | 1205HWa0000003206 | NEW | no | yes | 0 | 0.9 | no | - | no | Codetext | AllplanAttributes - ash D_Detailverweis: <undefiniert>; Sicherheitsklasse: -; Sonnenschutztyp: Movable; g-Wert: 0,51
 | H2 Ebene +2 | WA-HS | 1205Wa 0000354176 | yes | Codetext | m² | Zimmer- und Holzbauarbeiten | Wand | Außenwand 7-Schalig | WA-HS | 0 | A | 7.5 | 1205HWa0000003206 | NEW | no | yes | 0 | 0.9 | no | - | no | Codetext | AllplanAttributes - ash D_Detailverweis: <undefiniert>; Sicherheitsklasse: -; Sonnenschutztyp: Movable; g-Wert: 0,51
 | H2 Ebene +2 | WA-LB | 1205Wa 2005825379 | yes | Codetext | m² | Trockenbauarbeiten | Wand | Außenwand 7-Schalig | WA-LB | 0 | A | 7.5 | 1205HWa0000003244 | NEW | no | yes | 0 | 0.9 | no | - | no | Codetext | AllplanAttributes - ash D_Detailverweis: <undefiniert>; Sicherheitsklasse: -; Sonnenschutztyp: Movable; g-Wert: 0,51
 | H2 Ebene +2 | WA-DL | 1205Wa 2005825380 | yes | Codetext | m³ | Zimmer- und Holzbauarbeiten | Wand | Außenwand 7-Schalig | WA-DL | 0 | A | 7.5 | 1205HWa0000003244 | NEW | no | yes | 0 | 0.9 | no | - | no | Codetext | AllplanAttributes - ash D_Detailverweis: <undefiniert>; Sicherheitsklasse: -; Sonnenschutztyp: Movable; g-Wert: 0,51; ash W_laufende Nr. Statik: 8 (W 10.0)
 | H2 Ebene +2 | WA-DL | 1205Wa 2005825381 | yes | Codetext | m³ | Zimmer- und Holzbauarbeiten | Wand | Außenwand 7-Schalig | WA-DL | 0 | A | 7.5 | 1205HWa0000003244 | NEW | no | yes | 0 | 0.9 | no | - | no | Codetext | AllplanAttributes - ash D_Detailverweis: <undefiniert>; Sicherheitsklasse: -; Sonnenschutztyp: Movable; g-Wert: 0,51
 | H2 Ebene +2 | WA-DL | 1205Wa 2005825382 | yes | Codetext | m³ | Zimmer- und Holzbauarbeiten | Wand | Außenwand 7-Schalig | WA-DL | 0 | A | 7.5 | 1205HWa0000003244 | NEW | no | yes | 0 | 0.9 | no | - | no | Codetext | AllplanAttributes - ash D_Detailverweis: <undefiniert>; Sicherheitsklasse: -; Sonnenschutztyp: Movable; g-Wert: 0,51
 | H2 Ebene +2 | WA-LB | 1205Wa 2005825383 | yes | Codetext | m² | Trockenbauarbeiten | Wand | Außenwand 7-Schalig | WA-LB | 0 | A | 7.5 | 1205HWa0000003244 | NEW | no | yes | 0 | 0.9 | no | - | no | Codetext | AllplanAttributes - ash D_Detailverweis: <undefiniert>; Sicherheitsklasse: -; Sonnenschutztyp: Movable; g-Wert: 0,51
 | H2 Ebene +2 | WA-KL | 1205Wa 2005825384 | yes | Codetext | m² | Zimmer- und Holzbauarbeiten | Wand | Außenwand 7-Schalig | WA-KL | 0 | A | 7.5 | 1205HWa0000003244 | NEW | no | yes | 0 | 0.9 | no | - | no | Codetext | AllplanAttributes - ash D_Detailverweis: <undefiniert>; Sicherheitsklasse: -; Sonnenschutztyp: Movable; g-Wert: 0,51
 | H2 Ebene +2 | WA-TL | 1205Wa 2005825385 | yes | Codetext | m² | Zimmer- und Holzbauarbeiten | Wand | Außenwand 7-Schalig | WA-TL | 0 | A | 7.5 | 1205HWa0000003244 | NEW | no | yes | 0 | 0.9 | no | - | no | Codetext | AllplanAttributes - ash D_Detailverweis: <undefiniert>; Sicherheitsklasse: -; Sonnenschutztyp: Movable; g-Wert: 0,51
 | H2 Ebene +2 | WA-HS | 1205Wa 2005825386 | yes | Codetext | m² | Zimmer- und Holzbauarbeiten | Wand | Außenwand 7-Schalig | WA-HS | 0 | A | 7.5 | 1205HWa0000003244 | NEW | no | yes | 0 | 0.9 | no | - | no | Codetext | AllplanAttributes - ash D_Detailverweis: <undefiniert>; Sicherheitsklasse: -; Sonnenschutztyp: Movable; g-Wert: 0,51
 | H2 Ebene +2 | WA-LB | 1205Wa 2005827482 | yes | Codetext | m² | Trockenbauarbeiten | Wand | Außenwand 7-Schalig | WA-LB | 0 | A | 7.5 | 1205HWa0000003247 | NEW | no | yes | 0 | 0.9 | no | - | no | Codetext | AllplanAttributes - ash D_Detailverweis: <undefiniert>; Sicherheitsklasse: -; Sonnenschutztyp: Movable; g-Wert: 0,51
 | H2 Ebene +2 | WA-DL | 1205Wa 2005827483 | yes | Codetext | m³ | Zimmer- und Holzbauarbeiten | Wand | Außenwand 7-Schalig | WA-DL | 0 | A | 7.5 | 1205HWa0000003247 | NEW | no | yes | 0 | 0.9 | no | - | no | Codetext | AllplanAttributes - ash D_Detailverweis: DT D; ash D_Plannummer: D1851; Sicherheitsklasse: -; Sonnenschutztyp: Movable; g-Wert: 0,51; ash W_laufende Nr. Statik: 2 (W 2.0/ 2.1/ 2.2)
 | H2 Ebene +2 | WA-DL | 1205Wa 2005827484 | yes | Codetext | m³ | Zimmer- und Holzbauarbeiten | Wand | Außenwand 7-Schalig | WA-DL | 0 | A | 7.5 | 1205HWa0000003247 | NEW | no | yes | 0 | 0.9 | no | - | no | Codetext | AllplanAttributes - ash D_Detailverweis: <undefiniert>; Sicherheitsklasse: -; Sonnenschutztyp: Movable; g-Wert: 0,51
 | H2 Ebene +2 | WA-LB | 1205Wa 2005827485 | yes | Codetext | m² | Trockenbauarbeiten | Wand | Außenwand 7-Schalig | WA-LB | 0 | A | 7.5 | 1205HWa0000003247 | NEW | no | yes | 0 | 0.9 | no | - | no | Codetext | AllplanAttributes - ash D_Detailverweis: <undefiniert>; Sicherheitsklasse: -; Sonnenschutztyp: Movable; g-Wert: 0,51
 | H2 Ebene +2 | WA-KL | 1205Wa 2005827486 | yes | Codetext | m² | Zimmer- und Holzbauarbeiten | Wand | Außenwand 7-Schalig | WA-KL | 0 | A | 7.5 | 1205HWa0000003247 | NEW | no | yes | 0 | 0.9 | no | - | no | Codetext | AllplanAttributes - ash D_Detailverweis: <undefiniert>; Sicherheitsklasse: -; Sonnenschutztyp: Movable; g-Wert: 0,51
 | H2 Ebene +2 | WA-TL | 1205Wa 2005827487 | yes | Codetext | m² | Zimmer- und Holzbauarbeiten | Wand | Außenwand 7-Schalig | WA-TL | 0 | A | 7.5 | 1205HWa0000003247 | NEW | no | yes | 0 | 0.9 | no | - | no | Codetext | AllplanAttributes - ash D_Detailverweis: <undefiniert>; Sicherheitsklasse: -; Sonnenschutztyp: Movable; g-Wert: 0,51
 | H2 Ebene +2 | WA-HS | 1205Wa 2005827488 | yes | Codetext | m² | Zimmer- und Holzbauarbeiten | Wand | Außenwand 7-Schalig | WA-HS | 0 | A | 7.5 | 1205HWa0000003247 | NEW | no | yes | 0 | 0.9 | no | - | no | Codetext | AllplanAttributes - ash D_Detailverweis: <undefiniert>; Sicherheitsklasse: -; Sonnenschutztyp: Movable; g-Wert: 0,51
 | H2 Ebene +2 | WA-STB | 1205Wa 0000095327 | yes |  | m² | Zimmer- und Holzbauarbeiten | Wand | Außenwand 2-Schalig | WA-STB |  |  | 7.5 | 1205HWa0000095321 | NEW | no |  | 0 | 0.9 |  | 32 | AllplanAttributes - Ortscode_Geschoßbezeichnung: E02; ash D_Detailverweis: <undefiniert>; Sicherheitsklasse: -; Sonnenschutztyp: Movable; g-Wert: 0,51
 | H2 Ebene +2 | WA-DL | 1205Wa 0000095329 | yes |  | m³ | Zimmer- und Holzbauarbeiten | Wand | Außenwand 2-Schalig | WA-DL |  |  | 7.5 | 1205HWa0000095321 | NEW | no |  | 0 | 0.9 |  | 32 | AllplanAttributes - Ortscode_Geschoßbezeichnung: E02; ash D_Detailverweis: <undefiniert>; Sicherheitsklasse: -; Sonnenschutztyp: Movable; g-Wert: 0,51
 | H2 Ebene +2 | WA-LB | 1205Wa 0000095331 | yes |  | m² | Zimmer- und Holzbauarbeiten | Wand | Außenwand 2-Schalig | WA-LB |  |  | 7.5 | 1205HWa0000095321 | NEW | no |  | 0 | 0.9 |  | 32 | AllplanAttributes - Ortscode_Geschoßbezeichnung: E02; ash D_Detailverweis: <undefiniert>; Sicherheitsklasse: -; Sonnenschutztyp: Movable; g-Wert: 0,51
 | H2 Ebene +2 | WA-KL | 1205Wa 0000095333 | yes |  | m² | Zimmer- und Holzbauarbeiten | Wand | Außenwand 2-Schalig | WA-KL |  |  | 7.5 | 1205HWa0000095321 | NEW | no |  | 0 | 0.9 |  | 32 | AllplanAttributes - Ortscode_Geschoßbezeichnung: E02; ash D_Detailverweis: <undefiniert>; Sicherheitsklasse: -; Sonnenschutztyp: Movable; g-Wert: 0,51
 | H2 Ebene +2 | WA-TL | 1205Wa 0000095335 | yes |  | m² | Zimmer- und Holzbauarbeiten | Wand | Außenwand 2-Schalig | WA-TL |  |  | 7.5 | 1205HWa0000095321 | NEW | no |  | 0 | 0.9 |  | 32 | AllplanAttributes - Ortscode_Geschoßbezeichnung: E02; ash D_Detailverweis: <undefiniert>; Sicherheitsklasse: -; Sonnenschutztyp: Movable; g-Wert: 0,51
 | H2 Ebene +2 | WA-HS | 1205Wa 0000095337 | yes |  | m² | Zimmer- und Holzbauarbeiten | Wand | Außenwand 2-Schalig | WA-HS |  |  | 7.5 | 1205HWa0000095321 | NEW | no |  | 0 | 0.9 |  | 32 | AllplanAttributes - Ortscode_Geschoßbezeichnung: E02; ash D_Detailverweis: <undefiniert>; Sicherheitsklasse: -; Sonnenschutztyp: Movable; g-Wert: 0,51
 | H2 Ebene +2 | WA-LB | 1205Wa 2005858960 | yes | Codetext | m² | Trockenbauarbeiten | Wand | Außenwand 7-Schalig | WA-LB | 0 | A | 7.5 | 1205HWa0000094929 | NEW | no | yes | 0 | 0.9 | no | - | no | Codetext | AllplanAttributes - ash D_Detailverweis: <undefiniert>; Sicherheitsklasse: -; Sonnenschutztyp: Movable; g-Wert: 0,51
 | H2 Ebene +2 | WA-DL | 1205Wa 2005858961 | yes | Codetext | m³ | Zimmer- und Holzbauarbeiten | Wand | Außenwand 7-Schalig | WA-DL | 0 | A | 7.5 | 1205HWa0000094929 | NEW | no | yes | 0 | 0.9 | no | - | no | Codetext | AllplanAttributes - ash D_Detailverweis: <undefiniert>; Sicherheitsklasse: -; Sonnenschutztyp: Movable; g-Wert: 0,51; ash W_laufende Nr. Statik: 8 (W 10.0)
 | H2 Ebene +2 | WA-DL | 1205Wa 2005858962 | yes | Codetext | m³ | Zimmer- und Holzbauarbeiten | Wand | Außenwand 7-Schalig | WA-DL | 0 | A | 7.5 | 1205HWa0000094929 | NEW | no | yes | 0 | 0.9 | no | - | no | Codetext | AllplanAttributes - ash D_Detailverweis: <undefiniert>; Sicherheitsklasse: -; Sonnenschutztyp: Movable; g-Wert: 0,51
 | H2 Ebene +2 | WA-DL | 1205Wa 2005858963 | yes | Codetext | m³ | Zimmer- und Holzbauarbeiten | Wand | Außenwand 7-Schalig | WA-DL | 0 | A | 7.5 | 1205HWa0000094929 | NEW | no | yes | 0 | 0.9 | no | - | no | Codetext | AllplanAttributes - ash D_Detailverweis: <undefiniert>; Sicherheitsklasse: -; Sonnenschutztyp: Movable; g-Wert: 0,51
 | H2 Ebene +2 | WA-LB | 1205Wa 2005858964 | yes | Codetext | m² | Trockenbauarbeiten | Wand | Außenwand 7-Schalig | WA-LB | 0 | A | 7.5 | 1205HWa0000094929 | NEW | no | yes | 0 | 0.9 | no | - | no | Codetext | AllplanAttributes - ash D_Detailverweis: <undefiniert>; Sicherheitsklasse: -; Sonnenschutztyp: Movable; g-Wert: 0,51
 | H2 Ebene +2 | WA-KL | 1205Wa 2005858965 | yes | Codetext | m² | Zimmer- und Holzbauarbeiten | Wand | Außenwand 7-Schalig | WA-KL | 0 | A | 7.5 | 1205HWa0000094929 | NEW | no | yes | 0 | 0.9 | no | - | no | Codetext | AllplanAttributes - ash D_Detailverweis: <undefiniert>; Sicherheitsklasse: -; Sonnenschutztyp: Movable; g-Wert: 0,51
 | H2 Ebene +2 | WA-TL | 1205Wa 2005858966 | yes | Codetext | m² | Zimmer- und Holzbauarbeiten | Wand | Außenwand 7-Schalig | WA-TL | 0 | A | 7.5 | 1205HWa0000094929 | NEW | no | yes | 0 | 0.9 | no | - | no | Codetext | AllplanAttributes - ash D_Detailverweis: <undefiniert>; Sicherheitsklasse: -; Sonnenschutztyp: Movable; g-Wert: 0,51
 | H2 Ebene +2 | WA-HS | 1205Wa 2005858967 | yes | Codetext | m² | Zimmer- und Holzbauarbeiten | Wand | Außenwand 7-Schalig | WA-HS | 0 | A | 7.5 | 1205HWa0000094929 | NEW | no | yes | 0 | 0.9 | no | - | no | Codetext | AllplanAttributes - ash D_Detailverweis: <undefiniert>; Sicherheitsklasse: -; Sonnenschutztyp: Movable; g-Wert: 0,51
 | H2 Ebene +2 | WI-LB | 1205Wa 0000001812 | yes | Codetext | m² | Trockenbauarbeiten | Wand | Außenwand 2-Schalig | WI-LB | 0 | A | 7.5 | 1213HWa0812968153 | NEW | no | no | - | 0 | no |  | no | Codetext | AllplanAttributes - Ortscode_Geschoßbezeichnung: E00; ash_W_Trockenbau_Qualitäten: 9; Sicherheitsklasse: -
 | H2 Ebene +2 | WA-STB | 1205Wa 0000001814 | yes | Codetext | m² | Zimmer- und Holzbauarbeiten | Wand | Außenwand 2-Schalig | WA-STB | 0 | A | 7.5 | 1205HWa0000000032 | NEW | no | yes | 0 | 0 | no | 0 | no | Codetext | AllplanAttributes - Ortscode_Geschoßbezeichnung: E00; ash D_Detailverweis: <undefiniert>; Sicherheitsklasse: -
 | H2 Ebene +2 | WA-DL | 1205Wa 0000001816 | yes | Codetext | m³ | Zimmer- und Holzbauarbeiten | Wand | Außenwand 2-Schalig | WA-DL | 0 | A | 7.5 | 1205HWa0000000032 | NEW | no | yes | 0 | 0 | no | 0 | no | Codetext | AllplanAttributes - Ortscode_Geschoßbezeichnung: E00; ash D_Detailverweis: <undefiniert>; Sicherheitsklasse: -
 | H2 Ebene +2 | WA-LB | 1205Wa 0000001818 | yes | Codetext | m² | Trockenbauarbeiten | Wand | Außenwand 2-Schalig | WA-LB | 0 | A | 7.5 | 1205HWa0000000032 | NEW | no | yes | 0 | 0 | no | 0 | no | Codetext | AllplanAttributes - Ortscode_Geschoßbezeichnung: E00; ash D_Detailverweis: <undefiniert>; Sicherheitsklasse: -
 | H2 Ebene +2 | WA-KL | 1205Wa 0000001820 | yes | Codetext | m² | Zimmer- und Holzbauarbeiten | Wand | Außenwand 2-Schalig | WA-KL | 0 | A | 7.5 | 1205HWa0000000032 | NEW | no | yes | 0 | 0 | no | 0 | no | Codetext | AllplanAttributes - Ortscode_Geschoßbezeichnung: E00; ash D_Detailverweis: <undefiniert>; Sicherheitsklasse: -
 | H2 Ebene +2 | WA-TL | 1205Wa 0000001822 | yes | Codetext | m² | Zimmer- und Holzbauarbeiten | Wand | Außenwand 2-Schalig | WA-TL | 0 | A | 7.5 | 1205HWa0000000032 | NEW | no | yes | 0 | 0 | no | 0 | no | Codetext | AllplanAttributes - Ortscode_Geschoßbezeichnung: E00; ash D_Detailverweis: <undefiniert>; Sicherheitsklasse: -
 | H2 Ebene +2 | WA-HS | 1205Wa 2005866763 | yes | Codetext | m² | Zimmer- und Holzbauarbeiten | Wand | Außenwand 2-Schalig | WA-HS | 0 | A | 7.5 | 1205HWa0000000032 | NEW | no | yes | 0 | 0 | no | 0 | no | Codetext | AllplanAttributes - Ortscode_Geschoßbezeichnung: E00; ash D_Detailverweis: <undefiniert>; Sicherheitsklasse: -
 | H2 Ebene +2 | WA-LB | 1205Wa 0000178300 | yes | Codetext | m² | Trockenbauarbeiten | Wand | Außenwand 7-Schalig | WA-LB | 0 | A | 7.5 | 1205HWa0000178188 | NEW | no | yes | 0 | 0.9 | no | 32 | no | Codetext | AllplanAttributes - ash D_Detailverweis: <undefiniert>; Sicherheitsklasse: -; Sonnenschutztyp: Movable; g-Wert: 0,51
 | H2 Ebene +2 | WA-HD | 1205Wa 0000178299 | yes | Codetext | m³ | Zimmer- und Holzbauarbeiten | Wand | Außenwand 7-Schalig | WA-HD | 0 | A | 7.5 | 1205HWa0000178188 | NEW | no | yes | 0 | 0.9 | no | 32 | no | Codetext | AllplanAttributes - ash D_Detailverweis: <undefiniert>; Sicherheitsklasse: -; Sonnenschutztyp: Movable; g-Wert: 0,51; ash W_laufende Nr. Statik: 2 (W 2.0/ 2.1/ 2.2)
 | H2 Ebene +2 | WA-DL | 1205Wa 0000178298 | yes | Codetext | m³ | Zimmer- und Holzbauarbeiten | Wand | Außenwand 7-Schalig | WA-DL | 0 | A | 7.5 | 1205HWa0000178188 | NEW | no | yes | 0 | 0.9 | no | 32 | no | Codetext | AllplanAttributes - ash D_Detailverweis: <undefiniert>; Sicherheitsklasse: -; Sonnenschutztyp: Movable; g-Wert: 0,51
 | H2 Ebene +2 | WA-LB | 1205Wa 0000178297 | yes | Codetext | m² | Trockenbauarbeiten | Wand | Außenwand 7-Schalig | WA-LB | 0 | A | 7.5 | 1205HWa0000178188 | NEW | no | yes | 0 | 0.9 | no | 32 | no | Codetext | AllplanAttributes - ash D_Detailverweis: <undefiniert>; Sicherheitsklasse: -; Sonnenschutztyp: Movable; g-Wert: 0,51
 | H2 Ebene +2 | WA-KL | 1205Wa 0000178296 | yes | Codetext | m² | Zimmer- und Holzbauarbeiten | Wand | Außenwand 7-Schalig | WA-KL | 0 | A | 7.5 | 1205HWa0000178188 | NEW | no | yes | 0 | 0.9 | no | 32 | no | Codetext | AllplanAttributes - ash D_Detailverweis: <undefiniert>; Sicherheitsklasse: -; Sonnenschutztyp: Movable; g-Wert: 0,51
 | H2 Ebene +2 | WA-TL | 1205Wa 0000178295 | yes | Codetext | m² | Zimmer- und Holzbauarbeiten | Wand | Außenwand 7-Schalig | WA-TL | 0 | A | 7.5 | 1205HWa0000178188 | NEW | no | yes | 0 | 0.9 | no | 32 | no | Codetext | AllplanAttributes - ash D_Detailverweis: <undefiniert>; Sicherheitsklasse: -; Sonnenschutztyp: Movable; g-Wert: 0,51
 | H2 Ebene +2 | WA-HS | 1205Wa 0000178294 | yes | Codetext | m² | Zimmer- und Holzbauarbeiten | Wand | Außenwand 7-Schalig | WA-HS | 0 | A | 7.5 | 1205HWa0000178188 | NEW | no | yes | 0 | 0.9 | no | 32 | no | Codetext | AllplanAttributes - ash D_Detailverweis: FS13; ash D_Plannummer: D1854; Sicherheitsklasse: -; Sonnenschutztyp: Movable; g-Wert: 0,51
2x Gipsfaserplatte | H2 Ebene +2 | WA-LB | 1205Wa 2005867909 | yes |  | m² | Trockenbauarbeiten | Wand | 2x Gipsfaserplatte | WA-LB |  |  | 7.5 | 1205HWa0000000201 | NEW | no | yes | 0 | 0.9 |  | 32 | AllplanAttributes - ash D_Detailverweis: <undefiniert>; Sicherheitsklasse: -; Sonnenschutztyp: Movable; g-Wert: 0,51
Holzständer + Zwischendämmung | H2 Ebene +2 | WA-HD | 1205Wa 2005867907 | yes |  | m³ | Zimmer- und Holzbauarbeiten | Wand | Holzständer + Zwischendämmung | WA-HD |  |  | 7.5 | 1205HWa0000000201 | NEW | no | yes | 0 | 0.9 |  | 32 | AllplanAttributes - ash D_Detailverweis: <undefiniert>; Sicherheitsklasse: -; Sonnenschutztyp: Movable; g-Wert: 0,51; ash W_laufende Nr. Statik: 2 (W 2.0/ 2.1/ 2.2)
Staffel + Zwischendämmung | H2 Ebene +2 | WA-DL | 1205Wa 2005867908 | yes |  | m³ | Zimmer- und Holzbauarbeiten | Wand | Staffel + Zwischendämmung | WA-DL |  |  | 7.5 | 1205HWa0000000201 | NEW | no | yes | 0 | 0.9 |  | 32 | AllplanAttributes - ash D_Detailverweis: <undefiniert>; Sicherheitsklasse: -; Sonnenschutztyp: Movable; g-Wert: 0,51
 | H2 Ebene +2 | WA-LB | 1205Wa 2005867910 | yes | Codetext | m² | Trockenbauarbeiten | Wand | Außenwand 7-Schalig | WA-LB | 0 | A | 7.5 | 1205HWa0000000201 | NEW | no | yes | 0 | 0.9 | no | 32 | no | Codetext | AllplanAttributes - ash D_Detailverweis: <undefiniert>; Sicherheitsklasse: -; Sonnenschutztyp: Movable; g-Wert: 0,51
Konterlattung | H2 Ebene +2 | WA-KL | 1205Wa 2005867912 | yes |  | m² | Zimmer- und Holzbauarbeiten | Wand | Konterlattung | WA-KL |  |  | 7.5 | 1205HWa0000000201 | NEW | no | yes | 0 | 0.9 |  | 32 | AllplanAttributes - ash D_Detailverweis: <undefiniert>; Sicherheitsklasse: -; Sonnenschutztyp: Movable; g-Wert: 0,51
Traglattung | H2 Ebene +2 | WA-TL | 1205Wa 2005867913 | yes |  | m² | Zimmer- und Holzbauarbeiten | Wand | Traglattung | WA-TL |  |  | 7.5 | 1205HWa0000000201 | NEW | no | yes | 0 | 0.9 |  | 32 | AllplanAttributes - ash D_Detailverweis: <undefiniert>; Sicherheitsklasse: -; Sonnenschutztyp: Movable; g-Wert: 0,51
Holzschindel | H2 Ebene +2 | WA-HS | 1205Wa 2005867911 | yes |  | m² | Zimmer- und Holzbauarbeiten | Wand | Holzschindel | WA-HS |  |  | 7.5 | 1205HWa0000000201 | NEW | no | yes | 0 | 0.9 |  | 32 | AllplanAttributes - ash D_Detailverweis: <undefiniert>; Sicherheitsklasse: -; Sonnenschutztyp: Movable; g-Wert: 0,51
 | H2 Ebene +2 | WA-LB | 1205Wa 0000261308 | yes | Codetext | m² | Trockenbauarbeiten | Wand | Außenwand 7-Schalig | WA-LB | 0 | A | 7.5 | 1205HWa0000176634 | NEW | no | yes | 0 | 0.9 | no | 35 | no | Codetext | AllplanAttributes - ash D_Detailverweis: <undefiniert>; Sicherheitsklasse: -; Sonnenschutztyp: Movable; g-Wert: 0,51
 | H2 Ebene +2 | WA-HD | 1205Wa 0000261307 | yes | Codetext | m³ | Zimmer- und Holzbauarbeiten | Wand | Außenwand 7-Schalig | WA-HD | 0 | A | 7.5 | 1205HWa0000176634 | NEW | no | yes | 0 | 0.9 | no | 35 | no | Codetext | AllplanAttributes - ash D_Detailverweis: <undefiniert>; Sicherheitsklasse: -; Sonnenschutztyp: Movable; g-Wert: 0,51; ash W_laufende Nr. Statik: 2 (W 2.0/ 2.1/ 2.2)
 | H2 Ebene +2 | WA-DL | 1205Wa 0000261306 | yes | Codetext | m³ | Zimmer- und Holzbauarbeiten | Wand | Außenwand 7-Schalig | WA-DL | 0 | A | 7.5 | 1205HWa0000176634 | NEW | no | yes | 0 | 0.9 | no | 35 | no | Codetext | AllplanAttributes - ash D_Detailverweis: <undefiniert>; Sicherheitsklasse: -; Sonnenschutztyp: Movable; g-Wert: 0,51
 | H2 Ebene +2 | WA-LB | 1205Wa 0000261305 | yes | Codetext | m² | Trockenbauarbeiten | Wand | Außenwand 7-Schalig | WA-LB | 0 | A | 7.5 | 1205HWa0000176634 | NEW | no | yes | 0 | 0.9 | no | 35 | no | Codetext | AllplanAttributes - ash D_Detailverweis: <undefiniert>; Sicherheitsklasse: -; Sonnenschutztyp: Movable; g-Wert: 0,51
 | H2 Ebene +2 | WA-KL | 1205Wa 0000261304 | yes | Codetext | m² | Zimmer- und Holzbauarbeiten | Wand | Außenwand 7-Schalig | WA-KL | 0 | A | 7.5 | 1205HWa0000176634 | NEW | no | yes | 0 | 0.9 | no | 35 | no | Codetext | AllplanAttributes - ash D_Detailverweis: <undefiniert>; Sicherheitsklasse: -; Sonnenschutztyp: Movable; g-Wert: 0,51
 | H2 Ebene +2 | WA-TL | 1205Wa 0000261303 | yes | Codetext | m² | Zimmer- und Holzbauarbeiten | Wand | Außenwand 7-Schalig | WA-TL | 0 | A | 7.5 | 1205HWa0000176634 | NEW | no | yes | 0 | 0.9 | no | 35 | no | Codetext | AllplanAttributes - ash D_Detailverweis: <undefiniert>; Sicherheitsklasse: -; Sonnenschutztyp: Movable; g-Wert: 0,51
 | H2 Ebene +2 | WA-HS | 1205Wa 0000261302 | yes | Codetext | m² | Zimmer- und Holzbauarbeiten | Wand | Außenwand 7-Schalig | WA-HS | 0 | A | 7.5 | 1205HWa0000176634 | NEW | no | yes | 0 | 0.9 | no | 35 | no | Codetext | AllplanAttributes - ash D_Detailverweis: <undefiniert>; Sicherheitsklasse: -; Sonnenschutztyp: Movable; g-Wert: 0,51
 | H2 Ebene +2 | WA-LB | 1205Wa 0000002055 | yes | Codetext | m² | Trockenbauarbeiten | Wand | Außenwand 7-Schalig | WA-LB | 0 | A | 7.5 | 1205HWa0000176634 | NEW | no | yes | 0 | 0.9 | no | 35 | no | Codetext | AllplanAttributes - ash D_Detailverweis: <undefiniert>; Sicherheitsklasse: -; Sonnenschutztyp: Movable; g-Wert: 0,51
 | H2 Ebene +2 | WA-HD | 1205Wa 0000002051 | yes | Codetext | m³ | Zimmer- und Holzbauarbeiten | Wand | Außenwand 7-Schalig | WA-HD | 0 | A | 7.5 | 1205HWa0000176634 | NEW | no | yes | 0 | 0.9 | no | 35 | no | Codetext | AllplanAttributes - ash D_Detailverweis: <undefiniert>; Sicherheitsklasse: -; Sonnenschutztyp: Movable; g-Wert: 0,51; ash W_laufende Nr. Statik: 2 (W 2.0/ 2.1/ 2.2)
 | H2 Ebene +2 | WA-DL | 1205Wa 0000002047 | yes | Codetext | m³ | Zimmer- und Holzbauarbeiten | Wand | Außenwand 7-Schalig | WA-DL | 0 | A | 7.5 | 1205HWa0000176634 | NEW | no | yes | 0 | 0.9 | no | 35 | no | Codetext | AllplanAttributes - ash D_Detailverweis: <undefiniert>; Sicherheitsklasse: -; Sonnenschutztyp: Movable; g-Wert: 0,51
 | H2 Ebene +2 | WA-LB | 1205Wa 0000002043 | yes | Codetext | m² | Trockenbauarbeiten | Wand | Außenwand 7-Schalig | WA-LB | 0 | A | 7.5 | 1205HWa0000176634 | NEW | no | yes | 0 | 0.9 | no | 35 | no | Codetext | AllplanAttributes - ash D_Detailverweis: <undefiniert>; Sicherheitsklasse: -; Sonnenschutztyp: Movable; g-Wert: 0,51
 | H2 Ebene +2 | WA-KL | 1205Wa 0000002039 | yes | Codetext | m² | Zimmer- und Holzbauarbeiten | Wand | Außenwand 7-Schalig | WA-KL | 0 | A | 7.5 | 1205HWa0000176634 | NEW | no | yes | 0 | 0.9 | no | 35 | no | Codetext | AllplanAttributes - ash D_Detailverweis: <undefiniert>; Sicherheitsklasse: -; Sonnenschutztyp: Movable; g-Wert: 0,51
 | H2 Ebene +2 | WA-TL | 1205Wa 2005869526 | yes | Codetext | m² | Zimmer- und Holzbauarbeiten | Wand | Außenwand 7-Schalig | WA-TL | 0 | A | 7.5 | 1205HWa0000176634 | NEW | no | yes | 0 | 0.9 | no | 35 | no | Codetext | AllplanAttributes - ash D_Detailverweis: <undefiniert>; Sicherheitsklasse: -; Sonnenschutztyp: Movable; g-Wert: 0,51
 | H2 Ebene +2 | WA-HS | 1205Wa 2005869527 | yes | Codetext | m² | Zimmer- und Holzbauarbeiten | Wand | Außenwand 7-Schalig | WA-HS | 0 | A | 7.5 | 1205HWa0000176634 | NEW | no | yes | 0 | 0.9 | no | 35 | no | Codetext | AllplanAttributes - ash D_Detailverweis: <undefiniert>; Sicherheitsklasse: -; Sonnenschutztyp: Movable; g-Wert: 0,51
 | H2 Ebene +2 | WA-LB | 1205Wa 0000000738 | yes | Codetext | m² | Trockenbauarbeiten | Wand | Außenwand 7-Schalig | WA-LB | 0 | A | 7.5 | 1205HWa0000176634 | NEW | no | yes | 0 | 0.9 | no | 35 | no | Codetext | AllplanAttributes - ash D_Detailverweis: <undefiniert>; Sicherheitsklasse: -; Sonnenschutztyp: Movable; g-Wert: 0,51
 | H2 Ebene +2 | WA-HD | 1205Wa 0000000742 | yes | Codetext | m³ | Zimmer- und Holzbauarbeiten | Wand | Außenwand 7-Schalig | WA-HD | 0 | A | 7.5 | 1205HWa0000176634 | NEW | no | yes | 0 | 0.9 | no | 35 | no | Codetext | AllplanAttributes - ash D_Detailverweis: <undefiniert>; Sicherheitsklasse: -; Sonnenschutztyp: Movable; g-Wert: 0,51; ash W_laufende Nr. Statik: 2 (W 2.0/ 2.1/ 2.2)
 | H2 Ebene +2 | WA-DL | 1205Wa 0000000746 | yes | Codetext | m³ | Zimmer- und Holzbauarbeiten | Wand | Außenwand 7-Schalig | WA-DL | 0 | A | 7.5 | 1205HWa0000176634 | NEW | no | yes | 0 | 0.9 | no | 35 | no | Codetext | AllplanAttributes - ash D_Detailverweis: <undefiniert>; Sicherheitsklasse: -; Sonnenschutztyp: Movable; g-Wert: 0,51
 | H2 Ebene +2 | WA-LB | 1205Wa 0000000750 | yes | Codetext | m² | Trockenbauarbeiten | Wand | Außenwand 7-Schalig | WA-LB | 0 | A | 7.5 | 1205HWa0000176634 | NEW | no | yes | 0 | 0.9 | no | 35 | no | Codetext | AllplanAttributes - ash D_Detailverweis: <undefiniert>; Sicherheitsklasse: -; Sonnenschutztyp: Movable; g-Wert: 0,51
 | H2 Ebene +2 | WA-KL | 1205Wa 0000000754 | yes | Codetext | m² | Zimmer- und Holzbauarbeiten | Wand | Außenwand 7-Schalig | WA-KL | 0 | A | 7.5 | 1205HWa0000176634 | NEW | no | yes | 0 | 0.9 | no | 35 | no | Codetext | AllplanAttributes - ash D_Detailverweis: <undefiniert>; Sicherheitsklasse: -; Sonnenschutztyp: Movable; g-Wert: 0,51
 | H2 Ebene +2 | WA-TL | 1205Wa 2005869951 | yes | Codetext | m² | Zimmer- und Holzbauarbeiten | Wand | Außenwand 7-Schalig | WA-TL | 0 | A | 7.5 | 1205HWa0000176634 | NEW | no | yes | 0 | 0.9 | no | 35 | no | Codetext | AllplanAttributes - ash D_Detailverweis: <undefiniert>; Sicherheitsklasse: -; Sonnenschutztyp: Movable; g-Wert: 0,51
 | H2 Ebene +2 | WA-HS | 1205Wa 2005869952 | yes | Codetext | m² | Zimmer- und Holzbauarbeiten | Wand | Außenwand 7-Schalig | WA-HS | 0 | A | 7.5 | 1205HWa0000176634 | NEW | no | yes | 0 | 0.9 | no | 35 | no | Codetext | AllplanAttributes - ash D_Detailverweis: <undefiniert>; Sicherheitsklasse: -; Sonnenschutztyp: Movable; g-Wert: 0,51
 | H2 Ebene +2 | WA-LB | 1205Wa 0000000730 | yes | Codetext | m² | Trockenbauarbeiten | Wand | Außenwand 7-Schalig | WA-LB | 0 | A | 7.5 | 1205HWa0000176634 | NEW | no | yes | 0 | 0.9 | no | 35 | no | Codetext | AllplanAttributes - ash D_Detailverweis: <undefiniert>; Sicherheitsklasse: -; Sonnenschutztyp: Movable; g-Wert: 0,51
 | H2 Ebene +2 | WA-HD | 1205Wa 0000000726 | yes | Codetext | m³ | Zimmer- und Holzbauarbeiten | Wand | Außenwand 7-Schalig | WA-HD | 0 | A | 7.5 | 1205HWa0000176634 | NEW | no | yes | 0 | 0.9 | no | 35 | no | Codetext | AllplanAttributes - ash D_Detailverweis: <undefiniert>; Sicherheitsklasse: -; Sonnenschutztyp: Movable; g-Wert: 0,51; ash W_laufende Nr. Statik: 2 (W 2.0/ 2.1/ 2.2)
 | H2 Ebene +2 | WA-DL | 1205Wa 0000000722 | yes | Codetext | m³ | Zimmer- und Holzbauarbeiten | Wand | Außenwand 7-Schalig | WA-DL | 0 | A | 7.5 | 1205HWa0000176634 | NEW | no | yes | 0 | 0.9 | no | 35 | no | Codetext | AllplanAttributes - ash D_Detailverweis: <undefiniert>; Sicherheitsklasse: -; Sonnenschutztyp: Movable; g-Wert: 0,51
 | H2 Ebene +2 | WA-LB | 1205Wa 0000000718 | yes | Codetext | m² | Trockenbauarbeiten | Wand | Außenwand 7-Schalig | WA-LB | 0 | A | 7.5 | 1205HWa0000176634 | NEW | no | yes | 0 | 0.9 | no | 35 | no | Codetext | AllplanAttributes - ash D_Detailverweis: <undefiniert>; Sicherheitsklasse: -; Sonnenschutztyp: Movable; g-Wert: 0,51
 | H2 Ebene +2 | WA-KL | 1205Wa 0000000714 | yes | Codetext | m² | Zimmer- und Holzbauarbeiten | Wand | Außenwand 7-Schalig | WA-KL | 0 | A | 7.5 | 1205HWa0000176634 | NEW | no | yes | 0 | 0.9 | no | 35 | no | Codetext | AllplanAttributes - ash D_Detailverweis: <undefiniert>; Sicherheitsklasse: -; Sonnenschutztyp: Movable; g-Wert: 0,51
 | H2 Ebene +2 | WA-TL | 1205Wa 2005870369 | yes | Codetext | m² | Zimmer- und Holzbauarbeiten | Wand | Außenwand 7-Schalig | WA-TL | 0 | A | 7.5 | 1205HWa0000176634 | NEW | no | yes | 0 | 0.9 | no | 35 | no | Codetext | AllplanAttributes - ash D_Detailverweis: <undefiniert>; Sicherheitsklasse: -; Sonnenschutztyp: Movable; g-Wert: 0,51
 | H2 Ebene +2 | WA-HS | 1205Wa 2005870370 | yes | Codetext | m² | Zimmer- und Holzbauarbeiten | Wand | Außenwand 7-Schalig | WA-HS | 0 | A | 7.5 | 1205HWa0000176634 | NEW | no | yes | 0 | 0.9 | no | 35 | no | Codetext | AllplanAttributes - ash D_Detailverweis: <undefiniert>; Sicherheitsklasse: -; Sonnenschutztyp: Movable; g-Wert: 0,51
 | H2 Ebene +2 | WA-LB | 1205Wa 0000002572 | yes | Codetext | m² | Trockenbauarbeiten | Wand | Außenwand 7-Schalig | WA-LB | 0 | A | 7.5 | 1205HWa0000000821 | NEW | no | yes | 0 | 0.9 | no | 32 | no | Codetext | AllplanAttributes - ash D_Detailverweis: <undefiniert>; Sicherheitsklasse: -; Sonnenschutztyp: Movable; g-Wert: 0,51
 | H2 Ebene +2 | WA-HD | 1205Wa 0000002576 | yes | Codetext | m³ | Zimmer- und Holzbauarbeiten | Wand | Außenwand 7-Schalig | WA-HD | 0 | A | 7.5 | 1205HWa0000000821 | NEW | no | yes | 0 | 0.9 | no | 32 | no | Codetext | AllplanAttributes - ash D_Detailverweis: DT C; ash D_Plannummer: D1851; Sicherheitsklasse: -; Sonnenschutztyp: Movable; g-Wert: 0,51; ash W_laufende Nr. Statik: 2 (W 2.0/ 2.1/ 2.2)
 | H2 Ebene +2 | WA-DL | 1205Wa 0000002580 | yes | Codetext | m³ | Zimmer- und Holzbauarbeiten | Wand | Außenwand 7-Schalig | WA-DL | 0 | A | 7.5 | 1205HWa0000000821 | NEW | no | yes | 0 | 0.9 | no | 32 | no | Codetext | AllplanAttributes - ash D_Detailverweis: <undefiniert>; Sicherheitsklasse: -; Sonnenschutztyp: Movable; g-Wert: 0,51
 | H2 Ebene +2 | WA-LB | 1205Wa 0000002584 | yes | Codetext | m² | Trockenbauarbeiten | Wand | Außenwand 7-Schalig | WA-LB | 0 | A | 7.5 | 1205HWa0000000821 | NEW | no | yes | 0 | 0.9 | no | 32 | no | Codetext | AllplanAttributes - ash D_Detailverweis: <undefiniert>; Sicherheitsklasse: -; Sonnenschutztyp: Movable; g-Wert: 0,51
 | H2 Ebene +2 | WA-KL | 1205Wa 0000002588 | yes | Codetext | m² | Zimmer- und Holzbauarbeiten | Wand | Außenwand 7-Schalig | WA-KL | 0 | A | 7.5 | 1205HWa0000000821 | NEW | no | yes | 0 | 0.9 | no | 32 | no | Codetext | AllplanAttributes - ash D_Detailverweis: <undefiniert>; Sicherheitsklasse: -; Sonnenschutztyp: Movable; g-Wert: 0,51
 | H2 Ebene +2 | WA-TL | 1205Wa 0000002592 | yes | Codetext | m² | Zimmer- und Holzbauarbeiten | Wand | Außenwand 7-Schalig | WA-TL | 0 | A | 7.5 | 1205HWa0000000821 | NEW | no | yes | 0 | 0.9 | no | 32 | no | Codetext | AllplanAttributes - ash D_Detailverweis: <undefiniert>; Sicherheitsklasse: -; Sonnenschutztyp: Movable; g-Wert: 0,51
 | H2 Ebene +2 | WA-HS | 1205Wa 0000002596 | yes | Codetext | m² | Zimmer- und Holzbauarbeiten | Wand | Außenwand 7-Schalig | WA-HS | 0 | A | 7.5 | 1205HWa0000000821 | NEW | no | yes | 0 | 0.9 | no | 32 | no | Codetext | AllplanAttributes - ash D_Detailverweis: <undefiniert>; Sicherheitsklasse: -; Sonnenschutztyp: Movable; g-Wert: 0,51
2x Gipsfaserplatte | H2 Ebene +2 | WA-LB | 1205Wa 0000002517 | yes |  | m² | Trockenbauarbeiten | Wand | 2x Gipsfaserplatte | WA-LB |  |  | 7.5 | 1205HWa0000000826 | NEW | no | yes | 0 | 0.9 |  | 32 | AllplanAttributes - ash D_Detailverweis: <undefiniert>; Sicherheitsklasse: -; Sonnenschutztyp: Movable; g-Wert: 0,51
Holzständer + Zwischendämmung | H2 Ebene +2 | WA-DL | 1205Wa 0000002519 | yes |  | m³ | Zimmer- und Holzbauarbeiten | Wand | Holzständer + Zwischendämmung | WA-DL |  |  | 7.5 | 1205HWa0000000826 | NEW | no | yes | 0 | 0.9 |  | 32 | AllplanAttributes - ash D_Detailverweis: <undefiniert>; Sicherheitsklasse: -; Sonnenschutztyp: Movable; g-Wert: 0,51; ash W_laufende Nr. Statik: 2 (W 2.0/ 2.1/ 2.2)
Staffel + Zwischendämmung | H2 Ebene +2 | WA-DL | 1205Wa 0000002521 | yes |  | m³ | Zimmer- und Holzbauarbeiten | Wand | Staffel + Zwischendämmung | WA-DL |  |  | 7.5 | 1205HWa0000000826 | NEW | no | yes | 0 | 0.9 |  | 32 | AllplanAttributes - ash D_Detailverweis: <undefiniert>; Sicherheitsklasse: -; Sonnenschutztyp: Movable; g-Wert: 0,51
 | H2 Ebene +2 | WA-LB | 1205Wa 0000002523 | yes | Codetext | m² | Trockenbauarbeiten | Wand | Außenwand 7-Schalig | WA-LB | 0 | A | 7.5 | 1205HWa0000000826 | NEW | no | yes | 0 | 0.9 | no | 32 | no | Codetext | AllplanAttributes - ash D_Detailverweis: <undefiniert>; Sicherheitsklasse: -; Sonnenschutztyp: Movable; g-Wert: 0,51
Konterlattung | H2 Ebene +2 | WA-KL | 1205Wa 0000002525 | yes |  | m² | Zimmer- und Holzbauarbeiten | Wand | Konterlattung | WA-KL |  |  | 7.5 | 1205HWa0000000826 | NEW | no | yes | 0 | 0.9 |  | 32 | AllplanAttributes - ash D_Detailverweis: <undefiniert>; Sicherheitsklasse: -; Sonnenschutztyp: Movable; g-Wert: 0,51
Traglattung | H2 Ebene +2 | WA-TL | 1205Wa 0000002527 | yes |  | m² | Zimmer- und Holzbauarbeiten | Wand | Traglattung | WA-TL |  |  | 7.5 | 1205HWa0000000826 | NEW | no | yes | 0 | 0.9 |  | 32 | AllplanAttributes - ash D_Detailverweis: <undefiniert>; Sicherheitsklasse: -; Sonnenschutztyp: Movable; g-Wert: 0,51
Holzschindel | H2 Ebene +2 | WA-HS | 1205Wa 0000002529 | yes |  | m² | Zimmer- und Holzbauarbeiten | Wand | Holzschindel | WA-HS |  |  | 7.5 | 1205HWa0000000826 | NEW | no | yes | 0 | 0.9 |  | 32 | AllplanAttributes - ash D_Detailverweis: <undefiniert>; Sicherheitsklasse: -; Sonnenschutztyp: Movable; g-Wert: 0,51
2x Gipsfaserplatte | H2 Ebene +2 | WA-LB | 1205Wa 0000001945 | yes |  | m² | Trockenbauarbeiten | Wand | 2x Gipsfaserplatte | WA-LB |  |  | 7.5 | 1205HWa0000000826 | NEW | no | yes | 0 | 0.9 |  | 32 | AllplanAttributes - ash D_Detailverweis: <undefiniert>; Sicherheitsklasse: -; Sonnenschutztyp: Movable; g-Wert: 0,51
Holzständer + Zwischendämmung | H2 Ebene +2 | WA-DL | 1205Wa 0000001947 | yes |  | m³ | Zimmer- und Holzbauarbeiten | Wand | Holzständer + Zwischendämmung | WA-DL |  |  | 7.5 | 1205HWa0000000826 | NEW | no | yes | 0 | 0.9 |  | 32 | AllplanAttributes - ash D_Detailverweis: <undefiniert>; Sicherheitsklasse: -; Sonnenschutztyp: Movable; g-Wert: 0,51; ash W_laufende Nr. Statik: 2 (W 2.0/ 2.1/ 2.2)
Staffel + Zwischendämmung | H2 Ebene +2 | WA-DL | 1205Wa 0000001949 | yes |  | m³ | Zimmer- und Holzbauarbeiten | Wand | Staffel + Zwischendämmung | WA-DL |  |  | 7.5 | 1205HWa0000000826 | NEW | no | yes | 0 | 0.9 |  | 32 | AllplanAttributes - ash D_Detailverweis: <undefiniert>; Sicherheitsklasse: -; Sonnenschutztyp: Movable; g-Wert: 0,51
 | H2 Ebene +2 | WA-LB | 1205Wa 0000001951 | yes | Codetext | m² | Trockenbauarbeiten | Wand | Außenwand 7-Schalig | WA-LB | 0 | A | 7.5 | 1205HWa0000000826 | NEW | no | yes | 0 | 0.9 | no | 32 | no | Codetext | AllplanAttributes - ash D_Detailverweis: <undefiniert>; Sicherheitsklasse: -; Sonnenschutztyp: Movable; g-Wert: 0,51
Konterlattung | H2 Ebene +2 | WA-KL | 1205Wa 0000001953 | yes |  | m² | Zimmer- und Holzbauarbeiten | Wand | Konterlattung | WA-KL |  |  | 7.5 | 1205HWa0000000826 | NEW | no | yes | 0 | 0.9 |  | 32 | AllplanAttributes - ash D_Detailverweis: <undefiniert>; Sicherheitsklasse: -; Sonnenschutztyp: Movable; g-Wert: 0,51
Traglattung | H2 Ebene +2 | WA-TL | 1205Wa 2005869851 | yes |  | m² | Zimmer- und Holzbauarbeiten | Wand | Traglattung | WA-TL |  |  | 7.5 | 1205HWa0000000826 | NEW | no | yes | 0 | 0.9 |  | 32 | AllplanAttributes - ash D_Detailverweis: <undefiniert>; Sicherheitsklasse: -; Sonnenschutztyp: Movable; g-Wert: 0,51
Holzschindel | H2 Ebene +2 | WA-HS | 1205Wa 2005869852 | yes |  | m² | Zimmer- und Holzbauarbeiten | Wand | Holzschindel | WA-HS |  |  | 7.5 | 1205HWa0000000826 | NEW | no | yes | 0 | 0.9 |  | 32 | AllplanAttributes - ash D_Detailverweis: <undefiniert>; Sicherheitsklasse: -; Sonnenschutztyp: Movable; g-Wert: 0,51
2x Gipsfaserplatte | H2 Ebene +2 | WA-LB | 1205Wa 0000000764 | yes |  | m² | Trockenbauarbeiten | Wand | 2x Gipsfaserplatte | WA-LB |  |  | 7.5 | 1205HWa0000000826 | NEW | no | yes | 0 | 0.9 |  | 32 | AllplanAttributes - ash D_Detailverweis: <undefiniert>; Sicherheitsklasse: -; Sonnenschutztyp: Movable; g-Wert: 0,51
Holzständer + Zwischendämmung | H2 Ebene +2 | WA-DL | 1205Wa 0000000696 | yes |  | m³ | Zimmer- und Holzbauarbeiten | Wand | Holzständer + Zwischendämmung | WA-DL |  |  | 7.5 | 1205HWa0000000826 | NEW | no | yes | 0 | 0.9 |  | 32 | AllplanAttributes - ash D_Detailverweis: <undefiniert>; Sicherheitsklasse: -; Sonnenschutztyp: Movable; g-Wert: 0,51; ash W_laufende Nr. Statik: 2 (W 2.0/ 2.1/ 2.2)
Staffel + Zwischendämmung | H2 Ebene +2 | WA-DL | 1205Wa 0000000698 | yes |  | m³ | Zimmer- und Holzbauarbeiten | Wand | Staffel + Zwischendämmung | WA-DL |  |  | 7.5 | 1205HWa0000000826 | NEW | no | yes | 0 | 0.9 |  | 32 | AllplanAttributes - ash D_Detailverweis: <undefiniert>; Sicherheitsklasse: -; Sonnenschutztyp: Movable; g-Wert: 0,51
 | H2 Ebene +2 | WA-LB | 1205Wa 0000000700 | yes | Codetext | m² | Trockenbauarbeiten | Wand | Außenwand 7-Schalig | WA-LB | 0 | A | 7.5 | 1205HWa0000000826 | NEW | no | yes | 0 | 0.9 | no | 32 | no | Codetext | AllplanAttributes - ash D_Detailverweis: <undefiniert>; Sicherheitsklasse: -; Sonnenschutztyp: Movable; g-Wert: 0,51
Konterlattung | H2 Ebene +2 | WA-KL | 1205Wa 0000000702 | yes |  | m² | Zimmer- und Holzbauarbeiten | Wand | Konterlattung | WA-KL |  |  | 7.5 | 1205HWa0000000826 | NEW | no | yes | 0 | 0.9 |  | 32 | AllplanAttributes - ash D_Detailverweis: <undefiniert>; Sicherheitsklasse: -; Sonnenschutztyp: Movable; g-Wert: 0,51
Traglattung | H2 Ebene +2 | WA-TL | 1205Wa 2005870259 | yes |  | m² | Zimmer- und Holzbauarbeiten | Wand | Traglattung | WA-TL |  |  | 7.5 | 1205HWa0000000826 | NEW | no | yes | 0 | 0.9 |  | 32 | AllplanAttributes - ash D_Detailverweis: <undefiniert>; Sicherheitsklasse: -; Sonnenschutztyp: Movable; g-Wert: 0,51
Holzschindel | H2 Ebene +2 | WA-HS | 1205Wa 2005870260 | yes |  | m² | Zimmer- und Holzbauarbeiten | Wand | Holzschindel | WA-HS |  |  | 7.5 | 1205HWa0000000826 | NEW | no | yes | 0 | 0.9 |  | 32 | AllplanAttributes - ash D_Detailverweis: <undefiniert>; Sicherheitsklasse: -; Sonnenschutztyp: Movable; g-Wert: 0,51
2x Gipsfaserplatte | H2 Ebene +2 | WA-LB | 1205Wa 0000000734 | yes |  | m² | Trockenbauarbeiten | Wand | 2x Gipsfaserplatte | WA-LB |  |  | 7.5 | 1205HWa0000000826 | NEW | no | yes | 0 | 0.9 |  | 32 | AllplanAttributes - ash D_Detailverweis: <undefiniert>; Sicherheitsklasse: -; Sonnenschutztyp: Movable; g-Wert: 0,51
Holzständer + Zwischendämmung | H2 Ebene +2 | WA-DL | 1205Wa 0000000686 | yes |  | m³ | Zimmer- und Holzbauarbeiten | Wand | Holzständer + Zwischendämmung | WA-DL |  |  | 7.5 | 1205HWa0000000826 | NEW | no | yes | 0 | 0.9 |  | 32 | AllplanAttributes - ash D_Detailverweis: <undefiniert>; Sicherheitsklasse: -; Sonnenschutztyp: Movable; g-Wert: 0,51; ash W_laufende Nr. Statik: 2 (W 2.0/ 2.1/ 2.2)
Staffel + Zwischendämmung | H2 Ebene +2 | WA-DL | 1205Wa 0000000684 | yes |  | m³ | Zimmer- und Holzbauarbeiten | Wand | Staffel + Zwischendämmung | WA-DL |  |  | 7.5 | 1205HWa0000000826 | NEW | no | yes | 0 | 0.9 |  | 32 | AllplanAttributes - ash D_Detailverweis: <undefiniert>; Sicherheitsklasse: -; Sonnenschutztyp: Movable; g-Wert: 0,51
 | H2 Ebene +2 | WA-LB | 1205Wa 0000000682 | yes | Codetext | m² | Trockenbauarbeiten | Wand | Außenwand 7-Schalig | WA-LB | 0 | A | 7.5 | 1205HWa0000000826 | NEW | no | yes | 0 | 0.9 | no | 32 | no | Codetext | AllplanAttributes - ash D_Detailverweis: <undefiniert>; Sicherheitsklasse: -; Sonnenschutztyp: Movable; g-Wert: 0,51
Konterlattung | H2 Ebene +2 | WA-KL | 1205Wa 0000000680 | yes |  | m² | Zimmer- und Holzbauarbeiten | Wand | Konterlattung | WA-KL |  |  | 7.5 | 1205HWa0000000826 | NEW | no | yes | 0 | 0.9 |  | 32 | AllplanAttributes - ash D_Detailverweis: <undefiniert>; Sicherheitsklasse: -; Sonnenschutztyp: Movable; g-Wert: 0,51
Traglattung | H2 Ebene +2 | WA-TL | 1205Wa 2005870691 | yes |  | m² | Zimmer- und Holzbauarbeiten | Wand | Traglattung | WA-TL |  |  | 7.5 | 1205HWa0000000826 | NEW | no | yes | 0 | 0.9 |  | 32 | AllplanAttributes - ash D_Detailverweis: <undefiniert>; Sicherheitsklasse: -; Sonnenschutztyp: Movable; g-Wert: 0,51
Holzschindel | H2 Ebene +2 | WA-HS | 1205Wa 2005870692 | yes |  | m² | Zimmer- und Holzbauarbeiten | Wand | Holzschindel | WA-HS |  |  | 7.5 | 1205HWa0000000826 | NEW | no | yes | 0 | 0.9 |  | 32 | AllplanAttributes - ash D_Detailverweis: <undefiniert>; Sicherheitsklasse: -; Sonnenschutztyp: Movable; g-Wert: 0,51
 | H2 Ebene +2 | WA-LB | 1205Wa 0000000962 | yes | Codetext | m² | Trockenbauarbeiten | Wand | Außenwand 7-Schalig | WA-LB | 0 | A | 7.5 | 1205HWa0000000817 | NEW | no | yes | 0 | 0.9 | no | 32 | no | Codetext | AllplanAttributes - ash D_Detailverweis: <undefiniert>; Sicherheitsklasse: -; Sonnenschutztyp: Movable; g-Wert: 0,51
 | H2 Ebene +2 | WA-HD | 1205Wa 0000000958 | yes | Codetext | m³ | Zimmer- und Holzbauarbeiten | Wand | Außenwand 7-Schalig | WA-HD | 0 | A | 7.5 | 1205HWa0000000817 | NEW | no | yes | 0 | 0.9 | no | 32 | no | Codetext | AllplanAttributes - ash D_Detailverweis: <undefiniert>; Sicherheitsklasse: -; Sonnenschutztyp: Movable; g-Wert: 0,51; ash W_laufende Nr. Statik: 2 (W 2.0/ 2.1/ 2.2)
 | H2 Ebene +2 | WA-DL | 1205Wa 0000000938 | yes | Codetext | m³ | Zimmer- und Holzbauarbeiten | Wand | Außenwand 7-Schalig | WA-DL | 0 | A | 7.5 | 1205HWa0000000817 | NEW | no | yes | 0 | 0.9 | no | 32 | no | Codetext | AllplanAttributes - ash D_Detailverweis: <undefiniert>; Sicherheitsklasse: -; Sonnenschutztyp: Movable; g-Wert: 0,51
 | H2 Ebene +2 | WA-LB | 1205Wa 0000000942 | yes | Codetext | m² | Trockenbauarbeiten | Wand | Außenwand 7-Schalig | WA-LB | 0 | A | 7.5 | 1205HWa0000000817 | NEW | no | yes | 0 | 0.9 | no | 32 | no | Codetext | AllplanAttributes - ash D_Detailverweis: <undefiniert>; Sicherheitsklasse: -; Sonnenschutztyp: Movable; g-Wert: 0,51
 | H2 Ebene +2 | WA-KL | 1205Wa 0000000946 | yes | Codetext | m² | Zimmer- und Holzbauarbeiten | Wand | Außenwand 7-Schalig | WA-KL | 0 | A | 7.5 | 1205HWa0000000817 | NEW | no | yes | 0 | 0.9 | no | 32 | no | Codetext | AllplanAttributes - ash D_Detailverweis: <undefiniert>; Sicherheitsklasse: -; Sonnenschutztyp: Movable; g-Wert: 0,51
 | H2 Ebene +2 | WA-TL | 1205Wa 0000000950 | yes | Codetext | m² | Zimmer- und Holzbauarbeiten | Wand | Außenwand 7-Schalig | WA-TL | 0 | A | 7.5 | 1205HWa0000000817 | NEW | no | yes | 0 | 0.9 | no | 32 | no | Codetext | AllplanAttributes - ash D_Detailverweis: <undefiniert>; Sicherheitsklasse: -; Sonnenschutztyp: Movable; g-Wert: 0,51
 | H2 Ebene +2 | WA-HS | 1205Wa 0000000954 | yes | Codetext | m² | Zimmer- und Holzbauarbeiten | Wand | Außenwand 7-Schalig | WA-HS | 0 | A | 7.5 | 1205HWa0000000817 | NEW | no | yes | 0 | 0.9 | no | 32 | no | Codetext | AllplanAttributes - ash D_Detailverweis: <undefiniert>; Sicherheitsklasse: -; Sonnenschutztyp: Movable; g-Wert: 0,51
2x Gipsfaserplatte | H2 Ebene +2 | WA-LB | 1205Wa 0000000898 | yes |  | m² | Trockenbauarbeiten | Wand | 2x Gipsfaserplatte | WA-LB |  |  | 7.5 | 1205HWa0000000824 | NEW | no | yes | 0 | 0.9 |  | 32 | AllplanAttributes - ash D_Detailverweis: <undefiniert>; Sicherheitsklasse: -; Sonnenschutztyp: Movable; g-Wert: 0,51
Holzständer + Zwischendämmung | H2 Ebene +2 | WA-HD | 1205Wa 0000000966 | yes |  | m³ | Zimmer- und Holzbauarbeiten | Wand | Holzständer + Zwischendämmung | WA-HD |  |  | 7.5 | 1205HWa0000000824 | NEW | no | yes | 0 | 0.9 |  | 32 | AllplanAttributes - ash D_Detailverweis: <undefiniert>; Sicherheitsklasse: -; Sonnenschutztyp: Movable; g-Wert: 0,51; ash W_laufende Nr. Statik: 2 (W 2.0/ 2.1/ 2.2)
Staffel + Zwischendämmung | H2 Ebene +2 | WA-DL | 1205Wa 0000000964 | yes |  | m³ | Zimmer- und Holzbauarbeiten | Wand | Staffel + Zwischendämmung | WA-DL |  |  | 7.5 | 1205HWa0000000824 | NEW | no | yes | 0 | 0.9 |  | 32 | AllplanAttributes - ash D_Detailverweis: <undefiniert>; Sicherheitsklasse: -; Sonnenschutztyp: Movable; g-Wert: 0,51
 | H2 Ebene +2 | WA-LB | 1205Wa 0000000900 | yes | Codetext | m² | Trockenbauarbeiten | Wand | Außenwand 7-Schalig | WA-LB | 0 | A | 7.5 | 1205HWa0000000824 | NEW | no | yes | 0 | 0.9 | no | 32 | no | Codetext | AllplanAttributes - ash D_Detailverweis: <undefiniert>; Sicherheitsklasse: -; Sonnenschutztyp: Movable; g-Wert: 0,51
Konterlattung | H2 Ebene +2 | WA-KL | 1205Wa 0000000902 | yes |  | m² | Zimmer- und Holzbauarbeiten | Wand | Konterlattung | WA-KL |  |  | 7.5 | 1205HWa0000000824 | NEW | no | yes | 0 | 0.9 |  | 32 | AllplanAttributes - ash D_Detailverweis: <undefiniert>; Sicherheitsklasse: -; Sonnenschutztyp: Movable; g-Wert: 0,51
Traglattung | H2 Ebene +2 | WA-TL | 1205Wa 0000000904 | yes |  | m² | Zimmer- und Holzbauarbeiten | Wand | Traglattung | WA-TL |  |  | 7.5 | 1205HWa0000000824 | NEW | no | yes | 0 | 0.9 |  | 32 | AllplanAttributes - ash D_Detailverweis: <undefiniert>; Sicherheitsklasse: -; Sonnenschutztyp: Movable; g-Wert: 0,51
Holzschindel | H2 Ebene +2 | WA-HS | 1205Wa 0000000906 | yes |  | m² | Zimmer- und Holzbauarbeiten | Wand | Holzschindel | WA-HS |  |  | 7.5 | 1205HWa0000000824 | NEW | no | yes | 0 | 0.9 |  | 32 | AllplanAttributes - ash D_Detailverweis: <undefiniert>; Sicherheitsklasse: -; Sonnenschutztyp: Movable; g-Wert: 0,51
WV 1.1 | H2 Ebene +2 |  | 1213Sma0813716765 |  | VUK1 - Lichtleiste (ELT) | St | Trockenbauarbeiten | SmartPart | WV 1.1 |  |  |  | 7.5 |  |  |  |  | - | AllplanAttributes - Text1: WA; UK: 0 m; OK: 0 m; V6: 0 m; V7: 0 m; V8: 0 m; V9: 0; Länge: 1.2 m; Dicke: 0.025 m; Höhe: 0.15 m; Programmversion: 3.1; Text3: 0; Plugin_Bezeichnung: MainObject; Plugin_Objektname: SmartPartCompressed; Version: 1.1; Abstand_Öffn_Unten: 9.125 m; ash T_Feuchtebeständigkeit: nein; Feuerwiderstandsklasse~: nein
WV 1.1 | H2 Ebene +2 |  | 1213Sma0813716780 |  | VUK1 - Lichtleiste (ELT) | St | Trockenbauarbeiten | SmartPart | WV 1.1 |  |  |  | 7.5 |  |  |  |  | - | AllplanAttributes - Text1: WA; UK: 0 m; OK: 0 m; V6: 0 m; V7: 0 m; V8: 0 m; V9: 0; Länge: 1.2 m; Dicke: 0.025 m; Höhe: 0.15 m; Programmversion: 3.1; Text3: 0; Plugin_Bezeichnung: MainObject; Plugin_Objektname: SmartPartCompressed; Version: 1.1; Abstand_Öffn_Unten: 9.125 m; ash T_Feuchtebeständigkeit: nein; Feuerwiderstandsklasse~: nein
WV 1.1 | H2 Ebene +2 |  | 1213Sma0813716783 |  | VUK1 - Lichtleiste (ELT) | St | Trockenbauarbeiten | SmartPart | WV 1.1 |  |  |  | 3.75 |  |  |  |  | - | AllplanAttributes - Text1: WA2003; UK: 0 m; OK: 0 m; V6: 0 m; V7: 0 m; V8: 0 m; V9: 0; Länge: 1.2 m; Dicke: 0.025 m; Höhe: 0.15 m; Programmversion: 3.1; Text3: 0; Plugin_Bezeichnung: MainObject; Plugin_Objektname: SmartPartCompressed; Version: 1.1; Abstand_Öffn_Unten: 9.125 m; ash T_Feuchtebeständigkeit: nein; Feuerwiderstandsklasse~: nein
WV 1.1 | H2 Ebene +2 |  | 1213Sma0813716809 |  | VUK1 - Lichtleiste (ELT) | St | Trockenbauarbeiten | SmartPart | WV 1.1 |  |  |  | 3.75 |  |  |  |  | - | AllplanAttributes - Text1: WA2003; UK: 0 m; OK: 0 m; V6: 0 m; V7: 0 m; V8: 0 m; V9: 0; Länge: 1.2 m; Dicke: 0.025 m; Höhe: 0.15 m; Programmversion: 3.1; Text3: 0; Plugin_Bezeichnung: MainObject; Plugin_Objektname: SmartPartCompressed; Version: 1.1; Abstand_Öffn_Unten: 9.125 m; ash T_Feuchtebeständigkeit: nein; Feuerwiderstandsklasse~: nein
WV 1.1 | H2 Ebene +2 |  | 1213Sma0813717069 |  | VUK1 - Lichtleiste (ELT) | St | Trockenbauarbeiten | SmartPart | WV 1.1 |  |  |  | 3.75 |  |  |  |  | - | AllplanAttributes - Text1: WA2003; UK: 0 m; OK: 0 m; V6: 0 m; V7: 0 m; V8: 0 m; V9: 0; Länge: 1.2 m; Dicke: 0.025 m; Höhe: 0.15 m; Programmversion: 3.1; Text3: 0; Plugin_Bezeichnung: MainObject; Plugin_Objektname: SmartPartCompressed; Version: 1.1; Abstand_Öffn_Unten: 9.125 m; ash T_Feuchtebeständigkeit: nein; Feuerwiderstandsklasse~: nein
WV 1.1 | H2 Ebene +2 |  | 1213Sma0813717099 |  | VUK1 - Lichtleiste (ELT) | St | Trockenbauarbeiten | SmartPart | WV 1.1 |  |  |  | 3.75 |  |  |  |  | - | AllplanAttributes - Text1: WA2003; UK: 0 m; OK: 0 m; V6: 0 m; V7: 0 m; V8: 0 m; V9: 0; Länge: 1.2 m; Dicke: 0.025 m; Höhe: 0.15 m; Programmversion: 3.1; Text3: 0; Plugin_Bezeichnung: MainObject; Plugin_Objektname: SmartPartCompressed; Version: 1.1; Abstand_Öffn_Unten: 9.125 m; ash T_Feuchtebeständigkeit: nein; Feuerwiderstandsklasse~: nein
WV 1.1 | H2 Ebene +2 |  | 1213Sma0813716824 |  | VUK1 - Lichtleiste (ELT) | St | Trockenbauarbeiten | SmartPart | WV 1.1 |  |  |  | 3.75 |  |  |  |  | - | AllplanAttributes - Text1: WA2004; UK: 0 m; OK: 0 m; V6: 0 m; V7: 0 m; V8: 0 m; V9: 0; Länge: 1.2 m; Dicke: 0.025 m; Höhe: 0.15 m; Programmversion: 3.1; Text3: 0; Plugin_Bezeichnung: MainObject; Plugin_Objektname: SmartPartCompressed; Version: 1.1; Abstand_Öffn_Unten: 9.125 m; ash T_Feuchtebeständigkeit: nein; Feuerwiderstandsklasse~: nein
WV 1.1 | H2 Ebene +2 |  | 1213Sma0813716838 |  | VUK1 - Lichtleiste (ELT) | St | Trockenbauarbeiten | SmartPart | WV 1.1 |  |  |  | 3.75 |  |  |  |  | - | AllplanAttributes - Text1: WA2004; UK: 0 m; OK: 0 m; V6: 0 m; V7: 0 m; V8: 0 m; V9: 0; Länge: 1.2 m; Dicke: 0.025 m; Höhe: 0.15 m; Programmversion: 3.1; Text3: 0; Plugin_Bezeichnung: MainObject; Plugin_Objektname: SmartPartCompressed; Version: 1.1; Abstand_Öffn_Unten: 9.125 m; ash T_Feuchtebeständigkeit: nein; Feuerwiderstandsklasse~: nein
WV 1.1 | H2 Ebene +2 |  | 1213Sma0813716840 |  | VUK1 - Lichtleiste (ELT) | St | Trockenbauarbeiten | SmartPart | WV 1.1 |  |  |  | 3.75 |  |  |  |  | - | AllplanAttributes - Text1: WA2004; V6: 0 m; V7: 0 m; V8: 0 m; V9: 0; Länge: 1.2 m; Dicke: 0.025 m; Höhe: 0.15 m; Programmversion: 3.1; Text3: 0; Plugin_Bezeichnung: MainObject; Plugin_Objektname: SmartPartCompressed; Version: 1.1; Abstand_Öffn_Unten: 9.125 m; ash T_Feuchtebeständigkeit: nein; Feuerwiderstandsklasse~: nein
WV 1.1 | H2 Ebene +2 |  | 1213Sma0813717101 |  | VUK1 - Lichtleiste (ELT) | St | Trockenbauarbeiten | SmartPart | WV 1.1 |  |  |  | 3.75 |  |  |  |  | - | AllplanAttributes - Text1: WA2004; UK: 0 m; OK: 0 m; V6: 0 m; V7: 0 m; V8: 0 m; V9: 0; Länge: 1.2 m; Dicke: 0.025 m; Höhe: 0.15 m; Programmversion: 3.1; Text3: 0; Plugin_Bezeichnung: MainObject; Plugin_Objektname: SmartPartCompressed; Version: 1.1; Abstand_Öffn_Unten: 9.125 m; ash T_Feuchtebeständigkeit: nein; Feuerwiderstandsklasse~: nein
WV 1.1 | H2 Ebene +2 |  | 1213Sma0813716954 |  | VUK1 - Lichtleiste (ELT) | St | Trockenbauarbeiten | SmartPart | WV 1.1 |  |  |  | 3.75 |  |  |  |  | - | AllplanAttributes - Text1: WA2004; UK: 0 m; OK: 0 m; V6: 0 m; V7: 0 m; V8: 0 m; V9: 0; Länge: 1.2 m; Dicke: 0.025 m; Höhe: 0.15 m; Programmversion: 3.1; Text3: 0; Plugin_Bezeichnung: MainObject; Plugin_Objektname: SmartPartCompressed; Version: 1.1; Abstand_Öffn_Unten: 9.125 m; ash T_Feuchtebeständigkeit: nein; Feuerwiderstandsklasse~: nein
WV 1.1 | H2 Ebene +2 |  | 1213Sma0813716843 |  | VUK1 - Lichtleiste (ELT) | St | Trockenbauarbeiten | SmartPart | WV 1.1 |  |  |  | 3.75 |  |  |  |  | - | AllplanAttributes - Text1: WA2002; V6: 0 m; V7: 0 m; V8: 0 m; V9: 0; Länge: 1.2 m; Dicke: 0.025 m; Höhe: 0.15 m; Programmversion: 3.1; Text3: 0; Plugin_Bezeichnung: MainObject; Plugin_Objektname: SmartPartCompressed; Version: 1.1; Abstand_Öffn_Unten: 9.125 m; ash T_Feuchtebeständigkeit: nein; Feuerwiderstandsklasse~: nein
WV 1.1 | H2 Ebene +2 |  | 1213Sma0813716869 |  | VUK1 - Lichtleiste (ELT) | St | Trockenbauarbeiten | SmartPart | WV 1.1 |  |  |  | 3.75 |  |  |  |  | - | AllplanAttributes - Text1: WA2002; UK: 0 m; OK: 0 m; V6: 0 m; V7: 0 m; V8: 0 m; V9: 0; Länge: 1.2 m; Dicke: 0.025 m; Höhe: 0.15 m; Programmversion: 3.1; Text3: 0; Plugin_Bezeichnung: MainObject; Plugin_Objektname: SmartPartCompressed; Version: 1.1; Abstand_Öffn_Unten: 9.125 m; ash T_Feuchtebeständigkeit: nein; Feuerwiderstandsklasse~: nein
WV 1.1 | H2 Ebene +2 |  | 1213Sma0813716896 |  | VUK1 - Lichtleiste (ELT) | St | Trockenbauarbeiten | SmartPart | WV 1.1 |  |  |  | 3.75 |  |  |  |  | - | AllplanAttributes - Text1: WA2001; UK: 0 m; OK: 0 m; V6: 0 m; V7: 0 m; V8: 0 m; V9: 0; Länge: 1.2 m; Dicke: 0.025 m; Höhe: 0.15 m; Programmversion: 3.1; Text3: 0; Plugin_Bezeichnung: MainObject; Plugin_Objektname: SmartPartCompressed; Version: 1.1; Abstand_Öffn_Unten: 9.125 m; ash T_Feuchtebeständigkeit: nein; Feuerwiderstandsklasse~: nein
WV 1.1 | H2 Ebene +2 |  | 1213Sma0813716910 |  | VUK1 - Lichtleiste (ELT) | St | Trockenbauarbeiten | SmartPart | WV 1.1 |  |  |  | 3.75 |  |  |  |  | - | AllplanAttributes - Text1: WA2001; UK: 0 m; OK: 0 m; V6: 0 m; V7: 0 m; V8: 0 m; V9: 0; Länge: 1.2 m; Dicke: 0.025 m; Höhe: 0.15 m; Programmversion: 3.1; Text3: 0; Plugin_Bezeichnung: MainObject; Plugin_Objektname: SmartPartCompressed; Version: 1.1; Abstand_Öffn_Unten: 9.125 m; ash T_Feuchtebeständigkeit: nein; Feuerwiderstandsklasse~: nein
WV 1.1 | H2 Ebene +2 |  | 1213Sma0813717071 |  | VUK1 - Lichtleiste (ELT) | St | Trockenbauarbeiten | SmartPart | WV 1.1 |  |  |  | 3.75 |  |  |  |  | - | AllplanAttributes - Text1: WA2001; UK: 0 m; OK: 0 m; V6: 0 m; V7: 0 m; V8: 0 m; V9: 0; Länge: 1.2 m; Dicke: 0.025 m; Höhe: 0.15 m; Programmversion: 3.1; Text3: 0; Plugin_Bezeichnung: MainObject; Plugin_Objektname: SmartPartCompressed; Version: 1.1; Abstand_Öffn_Unten: 9.125 m; ash T_Feuchtebeständigkeit: nein; Feuerwiderstandsklasse~: nein
WV 1.1 | H2 Ebene +2 |  | 1213Sma0813717126 |  | VUK1 - Lichtleiste (ELT) | St | Trockenbauarbeiten | SmartPart | WV 1.1 |  |  |  | 3.75 |  |  |  |  | - | AllplanAttributes - Text1: WA2001; UK: 0 m; OK: 0 m; V6: 0 m; V7: 0 m; V8: 0 m; V9: 0; Länge: 1.2 m; Dicke: 0.025 m; Höhe: 0.15 m; Programmversion: 3.1; Text3: 0; Plugin_Bezeichnung: MainObject; Plugin_Objektname: SmartPartCompressed; Version: 1.1; Abstand_Öffn_Unten: 9.125 m; ash T_Feuchtebeständigkeit: nein; Feuerwiderstandsklasse~: nein
WV 1.1 | H2 Ebene +2 |  | 1213Sma0813717141 |  | VUK1 - Lichtleiste (ELT) | St | Trockenbauarbeiten | SmartPart | WV 1.1 |  |  |  | 3.75 |  |  |  |  | - | AllplanAttributes - Text1: WA2001; UK: 0 m; OK: 0 m; V6: 0 m; V7: 0 m; V8: 0 m; V9: 0; Länge: 1.2 m; Dicke: 0.025 m; Höhe: 0.15 m; Programmversion: 3.1; Text3: 0; Plugin_Bezeichnung: MainObject; Plugin_Objektname: SmartPartCompressed; Version: 1.1; Abstand_Öffn_Unten: 9.125 m; ash T_Feuchtebeständigkeit: nein; Feuerwiderstandsklasse~: nein
WV 1.1 | H2 Ebene +2 |  | 1213Sma0813717143 |  | VUK1 - Lichtleiste (ELT) | St | Trockenbauarbeiten | SmartPart | WV 1.1 |  |  |  | 3.75 |  |  |  |  | - | AllplanAttributes - Text1: WA2001; UK: 0 m; OK: 0 m; V6: 0 m; V7: 0 m; V8: 0 m; V9: 0; Länge: 1.2 m; Dicke: 0.025 m; Höhe: 0.15 m; Programmversion: 3.1; Text3: 0; Plugin_Bezeichnung: MainObject; Plugin_Objektname: SmartPartCompressed; Version: 1.1; Abstand_Öffn_Unten: 9.125 m; ash T_Feuchtebeständigkeit: nein; Feuerwiderstandsklasse~: nein
WV 1.1 | H2 Ebene +2 |  | 1213Sma0813717169 |  | VUK1 - Lichtleiste (ELT) | St | Trockenbauarbeiten | SmartPart | WV 1.1 |  |  |  | 3.75 |  |  |  |  | - | AllplanAttributes - Text1: WA2001; UK: 0 m; OK: 0 m; V6: 0 m; V7: 0 m; V8: 0 m; V9: 0; Länge: 1.2 m; Dicke: 0.025 m; Höhe: 0.15 m; Programmversion: 3.1; Text3: 0; Plugin_Bezeichnung: MainObject; Plugin_Objektname: SmartPartCompressed; Version: 1.1; Abstand_Öffn_Unten: 9.125 m; ash T_Feuchtebeständigkeit: nein; Feuerwiderstandsklasse~: nein
WV 1.1 | H2 Ebene +2 |  | 1213Sma0813717308 |  | VUK1 - Lichtleiste (ELT) | St | Trockenbauarbeiten | SmartPart | WV 1.1 |  |  |  | 3.75 |  |  |  |  | - | AllplanAttributes - Text1: WA2001; UK: 0 m; OK: 0 m; V6: 0 m; V7: 0 m; V8: 0 m; V9: 0; Länge: 1.2 m; Dicke: 0.025 m; Höhe: 0.15 m; Programmversion: 3.1; Text3: 0; Plugin_Bezeichnung: MainObject; Plugin_Objektname: SmartPartCompressed; Version: 1.1; Abstand_Öffn_Unten: 9.125 m; ash T_Feuchtebeständigkeit: nein; Feuerwiderstandsklasse~: nein
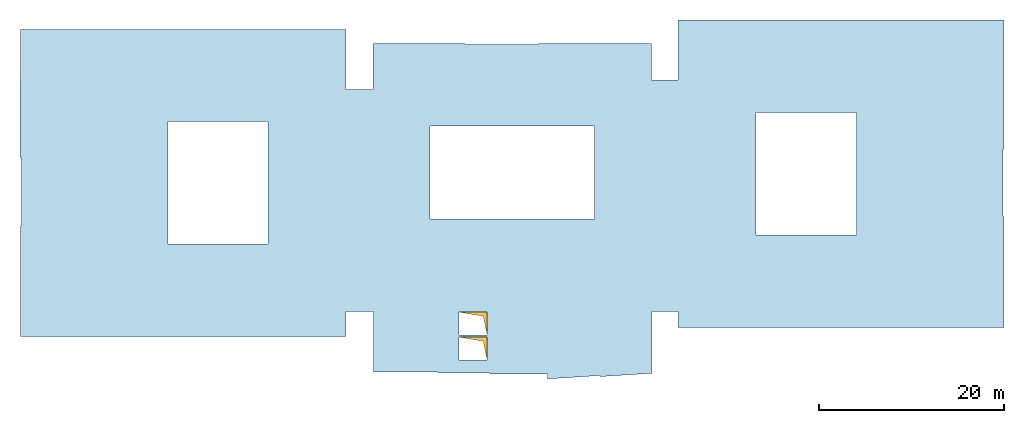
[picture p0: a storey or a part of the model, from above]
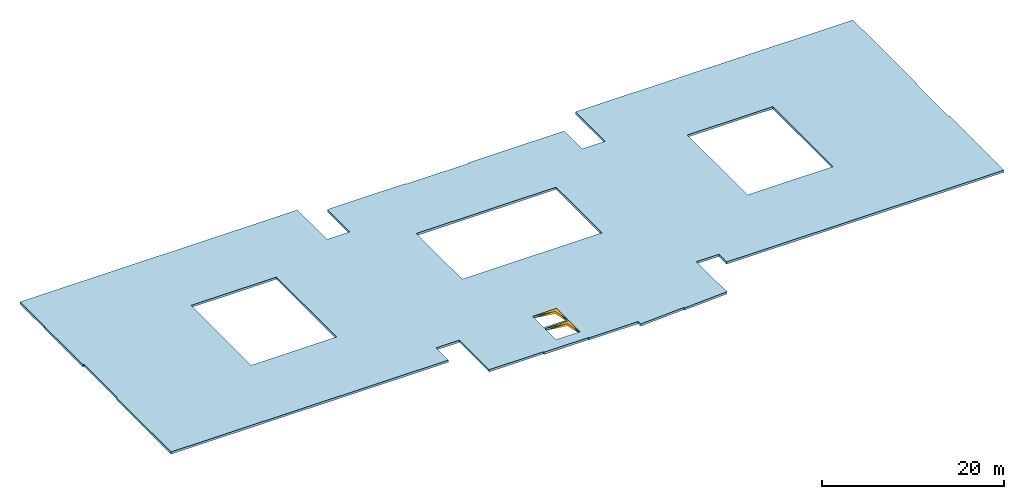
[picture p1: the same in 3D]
Properties of the parts of a building model (IFC4), part 53 of 80

# IfcWall (6826)
Name | In | Material | Allright_Bauteil_ID | 2D Interaktion | Codetext | Abrechnungsart | Gewerk | Objektname | Bezeichnung | AllplanAttributes, Material | Typ = SurfaceSpreadOfFlame | Brandschutzklasse | OKFF | P_ID | Status | LoadBearing | IsExternal | FireRating | ThermalTransmittance (W/K/m2) | Combustible | AcousticRating | Compartmentation | Reference
WV 1.1 | H2 Ebene +2 |  | 1213Sma0813717322 |  | VUK1 - Lichtleiste (ELT) | St | Trockenbauarbeiten | SmartPart | WV 1.1 |  |  |  | 3.75 |  |  |  |  | - | AllplanAttributes - Text1: WA2001; UK: 0 m; OK: 0 m; V6: 0 m; V7: 0 m; V8: 0 m; V9: 0; Länge: 1.2 m; Dicke: 0.025 m; Höhe: 0.15 m; Programmversion: 3.1; Text3: 0; Plugin_Bezeichnung: MainObject; Plugin_Objektname: SmartPartCompressed; Version: 1.1; Abstand_Öffn_Unten: 9.125 m; ash T_Feuchtebeständigkeit: nein; Feuerwiderstandsklasse~: nein
WV 1.1 | H2 Ebene +2 |  | 1213Sma0813717324 |  | VUK1 - Lichtleiste (ELT) | St | Trockenbauarbeiten | SmartPart | WV 1.1 |  |  |  | 3.75 |  |  |  |  | - | AllplanAttributes - Text1: WA2001; UK: 0 m; OK: 0 m; V6: 0 m; V7: 0 m; V8: 0 m; V9: 0; Länge: 1.2 m; Dicke: 0.025 m; Höhe: 0.15 m; Programmversion: 3.1; Text3: 0; Plugin_Bezeichnung: MainObject; Plugin_Objektname: SmartPartCompressed; Version: 1.1; Abstand_Öffn_Unten: 9.125 m; ash T_Feuchtebeständigkeit: nein; Feuerwiderstandsklasse~: nein
WV 1.1 | H2 Ebene +2 |  | 1213Sma0813717350 |  | VUK1 - Lichtleiste (ELT) | St | Trockenbauarbeiten | SmartPart | WV 1.1 |  |  |  | 3.75 |  |  |  |  | - | AllplanAttributes - Text1: WA2001; UK: 0 m; OK: 0 m; V6: 0 m; V7: 0 m; V8: 0 m; V9: 0; Länge: 1.2 m; Dicke: 0.025 m; Höhe: 0.15 m; Programmversion: 3.1; Text3: 0; Plugin_Bezeichnung: MainObject; Plugin_Objektname: SmartPartCompressed; Version: 1.1; Abstand_Öffn_Unten: 9.125 m; ash T_Feuchtebeständigkeit: nein; Feuerwiderstandsklasse~: nein
WV 1.1 | H2 Ebene +2 |  | 1213Sma0813717352 |  | VUK1 - Lichtleiste (ELT) | St | Trockenbauarbeiten | SmartPart | WV 1.1 |  |  |  | 3.75 |  |  |  |  | - | AllplanAttributes - Text1: WA2001; UK: 0 m; OK: 0 m; V6: 0 m; V7: 0 m; V8: 0 m; V9: 0; Länge: 1.2 m; Dicke: 0.025 m; Höhe: 0.15 m; Programmversion: 3.1; Text3: 0; Plugin_Bezeichnung: MainObject; Plugin_Objektname: SmartPartCompressed; Version: 1.1; Abstand_Öffn_Unten: 9.125 m; ash T_Feuchtebeständigkeit: nein; Feuerwiderstandsklasse~: nein
WV 1.1 | H2 Ebene +2 |  | 1213Sma0813717378 |  | VUK1 - Lichtleiste (ELT) | St | Trockenbauarbeiten | SmartPart | WV 1.1 |  |  |  | 3.75 |  |  |  |  | - | AllplanAttributes - Text1: WA2001; UK: 0 m; OK: 0 m; V6: 0 m; V7: 0 m; V8: 0 m; V9: 0; Länge: 1.2 m; Dicke: 0.025 m; Höhe: 0.15 m; Programmversion: 3.1; Text3: 0; Plugin_Bezeichnung: MainObject; Plugin_Objektname: SmartPartCompressed; Version: 1.1; Abstand_Öffn_Unten: 9.125 m; ash T_Feuchtebeständigkeit: nein; Feuerwiderstandsklasse~: nein
WV 1.1 | H2 Ebene +2 |  | 1213Sma0813717392 |  | VUK1 - Lichtleiste (ELT) | St | Trockenbauarbeiten | SmartPart | WV 1.1 |  |  |  | 3.75 |  |  |  |  | - | AllplanAttributes - Text1: WA2001; UK: 0 m; OK: 0 m; V6: 0 m; V7: 0 m; V8: 0 m; V9: 0; Länge: 1.2 m; Dicke: 0.025 m; Höhe: 0.15 m; Programmversion: 3.1; Text3: 0; Plugin_Bezeichnung: MainObject; Plugin_Objektname: SmartPartCompressed; Version: 1.1; Abstand_Öffn_Unten: 9.125 m; ash T_Feuchtebeständigkeit: nein; Feuerwiderstandsklasse~: nein
WV 1.1 | H2 Ebene +2 |  | 1213Sma0813717394 |  | VUK1 - Lichtleiste (ELT) | St | Trockenbauarbeiten | SmartPart | WV 1.1 |  |  |  | 3.75 |  |  |  |  | - | AllplanAttributes - Text1: WA2001; UK: 0 m; OK: 0 m; V6: 0 m; V7: 0 m; V8: 0 m; V9: 0; Länge: 1.2 m; Dicke: 0.025 m; Höhe: 0.15 m; Programmversion: 3.1; Text3: 0; Plugin_Bezeichnung: MainObject; Plugin_Objektname: SmartPartCompressed; Version: 1.1; Abstand_Öffn_Unten: 9.125 m; ash T_Feuchtebeständigkeit: nein; Feuerwiderstandsklasse~: nein
WV 1.1 | H2 Ebene +2 |  | 1213Sma0813717420 |  | VUK1 - Lichtleiste (ELT) | St | Trockenbauarbeiten | SmartPart | WV 1.1 |  |  |  | 3.75 |  |  |  |  | - | AllplanAttributes - Text1: WA2001; UK: 0 m; OK: 0 m; V6: 0 m; V7: 0 m; V8: 0 m; V9: 0; Länge: 1.2 m; Dicke: 0.025 m; Höhe: 0.15 m; Programmversion: 3.1; Text3: 0; Plugin_Bezeichnung: MainObject; Plugin_Objektname: SmartPartCompressed; Version: 1.1; Abstand_Öffn_Unten: 9.125 m; ash T_Feuchtebeständigkeit: nein; Feuerwiderstandsklasse~: nein
WV 1.1 | H2 Ebene +2 |  | 1213Sma0813717422 |  | VUK1 - Lichtleiste (ELT) | St | Trockenbauarbeiten | SmartPart | WV 1.1 |  |  |  | 3.75 |  |  |  |  | - | AllplanAttributes - Text1: WA2001; UK: 0 m; OK: 0 m; V6: 0 m; V7: 0 m; V8: 0 m; V9: 0; Länge: 1.2 m; Dicke: 0.025 m; Höhe: 0.15 m; Programmversion: 3.1; Text3: 0; Plugin_Bezeichnung: MainObject; Plugin_Objektname: SmartPartCompressed; Version: 1.1; Abstand_Öffn_Unten: 9.125 m; ash T_Feuchtebeständigkeit: nein; Feuerwiderstandsklasse~: nein
WV 1.1 | H2 Ebene +2 |  | 1213Sma0813717448 |  | VUK1 - Lichtleiste (ELT) | St | Trockenbauarbeiten | SmartPart | WV 1.1 |  |  |  | 3.75 |  |  |  |  | - | AllplanAttributes - Text1: WA2001; UK: 0 m; OK: 0 m; V6: 0 m; V7: 0 m; V8: 0 m; V9: 0; Länge: 1.2 m; Dicke: 0.025 m; Höhe: 0.15 m; Programmversion: 3.1; Text3: 0; Plugin_Bezeichnung: MainObject; Plugin_Objektname: SmartPartCompressed; Version: 1.1; Abstand_Öffn_Unten: 9.125 m; ash T_Feuchtebeständigkeit: nein; Feuerwiderstandsklasse~: nein
WV 1.1 | H2 Ebene +2 |  | 1213Sma0813717450 |  | VUK1 - Lichtleiste (ELT) | St | Trockenbauarbeiten | SmartPart | WV 1.1 |  |  |  | 3.75 |  |  |  |  | - | AllplanAttributes - Text1: WA2001; UK: 0 m; OK: 0 m; V6: 0 m; V7: 0 m; V8: 0 m; V9: 0; Länge: 1.2 m; Dicke: 0.025 m; Höhe: 0.15 m; Programmversion: 3.1; Text3: 0; Plugin_Bezeichnung: MainObject; Plugin_Objektname: SmartPartCompressed; Version: 1.1; Abstand_Öffn_Unten: 9.125 m; ash T_Feuchtebeständigkeit: nein; Feuerwiderstandsklasse~: nein
WV 1.1 | H2 Ebene +2 |  | 1213Sma0813717476 |  | VUK1 - Lichtleiste (ELT) | St | Trockenbauarbeiten | SmartPart | WV 1.1 |  |  |  | 3.75 |  |  |  |  | - | AllplanAttributes - Text1: WA2001; UK: 0 m; OK: 0 m; V6: 0 m; V7: 0 m; V8: 0 m; V9: 0; Länge: 1.2 m; Dicke: 0.025 m; Höhe: 0.15 m; Programmversion: 3.1; Text3: 0; Plugin_Bezeichnung: MainObject; Plugin_Objektname: SmartPartCompressed; Version: 1.1; Abstand_Öffn_Unten: 9.125 m; ash T_Feuchtebeständigkeit: nein; Feuerwiderstandsklasse~: nein
WV 1.1 | H2 Ebene +2 |  | 1213Sma0813717559 |  | VUK1 - Lichtleiste (ELT) | St | Trockenbauarbeiten | SmartPart | WV 1.1 |  |  |  | 3.75 |  |  |  |  | - | AllplanAttributes - Text1: WA2001; UK: 0 m; OK: 0 m; V6: 0 m; V7: 0 m; V8: 0 m; V9: 0; Länge: 1.2 m; Dicke: 0.025 m; Höhe: 0.15 m; Programmversion: 3.1; Text3: 0; Plugin_Bezeichnung: MainObject; Plugin_Objektname: SmartPartCompressed; Version: 1.1; Abstand_Öffn_Unten: 9.125 m; ash T_Feuchtebeständigkeit: nein; Feuerwiderstandsklasse~: nein
WV 1.1 | H2 Ebene +2 |  | 1213Sma0813717561 |  | VUK1 - Lichtleiste (ELT) | St | Trockenbauarbeiten | SmartPart | WV 1.1 |  |  |  | 3.75 |  |  |  |  | - | AllplanAttributes - Text1: WA2001; UK: 0 m; OK: 0 m; V6: 0 m; V7: 0 m; V8: 0 m; V9: 0; Länge: 1.2 m; Dicke: 0.025 m; Höhe: 0.15 m; Programmversion: 3.1; Text3: 0; Plugin_Bezeichnung: MainObject; Plugin_Objektname: SmartPartCompressed; Version: 1.1; Abstand_Öffn_Unten: 9.125 m; ash T_Feuchtebeständigkeit: nein; Feuerwiderstandsklasse~: nein
WV 1.1 | H2 Ebene +2 |  | 1213Sma0813717563 |  | VUK1 - Lichtleiste (ELT) | St | Trockenbauarbeiten | SmartPart | WV 1.1 |  |  |  | 3.75 |  |  |  |  | - | AllplanAttributes - Text1: WA2001; UK: 0 m; OK: 0 m; V6: 0 m; V7: 0 m; V8: 0 m; V9: 0; Länge: 1.2 m; Dicke: 0.025 m; Höhe: 0.15 m; Programmversion: 3.1; Text3: 0; Plugin_Bezeichnung: MainObject; Plugin_Objektname: SmartPartCompressed; Version: 1.1; Abstand_Öffn_Unten: 9.125 m; ash T_Feuchtebeständigkeit: nein; Feuerwiderstandsklasse~: nein
WV 1.1 | H2 Ebene +2 |  | 1213Sma0813717565 |  | VUK1 - Lichtleiste (ELT) | St | Trockenbauarbeiten | SmartPart | WV 1.1 |  |  |  | 3.75 |  |  |  |  | - | AllplanAttributes - Text1: WA2001; UK: 0 m; OK: 0 m; V6: 0 m; V7: 0 m; V8: 0 m; V9: 0; Länge: 1.2 m; Dicke: 0.025 m; Höhe: 0.15 m; Programmversion: 3.1; Text3: 0; Plugin_Bezeichnung: MainObject; Plugin_Objektname: SmartPartCompressed; Version: 1.1; Abstand_Öffn_Unten: 9.125 m; ash T_Feuchtebeständigkeit: nein; Feuerwiderstandsklasse~: nein
WV 1.1 | H2 Ebene +2 |  | 1213Sma0813717567 |  | VUK1 - Lichtleiste (ELT) | St | Trockenbauarbeiten | SmartPart | WV 1.1 |  |  |  | 3.75 |  |  |  |  | - | AllplanAttributes - Text1: WA2001; UK: 0 m; OK: 0 m; V6: 0 m; V7: 0 m; V8: 0 m; V9: 0; Länge: 1.2 m; Dicke: 0.025 m; Höhe: 0.15 m; Programmversion: 3.1; Text3: 0; Plugin_Bezeichnung: MainObject; Plugin_Objektname: SmartPartCompressed; Version: 1.1; Abstand_Öffn_Unten: 9.125 m; ash T_Feuchtebeständigkeit: nein; Feuerwiderstandsklasse~: nein
WV 1.1 | H2 Ebene +2 |  | 1213Sma0813717569 |  | VUK1 - Lichtleiste (ELT) | St | Trockenbauarbeiten | SmartPart | WV 1.1 |  |  |  | 3.75 |  |  |  |  | - | AllplanAttributes - Text1: WA2001; UK: 0 m; OK: 0 m; V6: 0 m; V7: 0 m; V8: 0 m; V9: 0; Länge: 1.2 m; Dicke: 0.025 m; Höhe: 0.15 m; Programmversion: 3.1; Text3: 0; Plugin_Bezeichnung: MainObject; Plugin_Objektname: SmartPartCompressed; Version: 1.1; Abstand_Öffn_Unten: 9.125 m; ash T_Feuchtebeständigkeit: nein; Feuerwiderstandsklasse~: nein
WV 1.1 | H2 Ebene +2 |  | 1213Sma0813717571 |  | VUK1 - Lichtleiste (ELT) | St | Trockenbauarbeiten | SmartPart | WV 1.1 |  |  |  | 3.75 |  |  |  |  | - | AllplanAttributes - Text1: WA2001; UK: 0 m; OK: 0 m; V6: 0 m; V7: 0 m; V8: 0 m; V9: 0; Länge: 1.2 m; Dicke: 0.025 m; Höhe: 0.15 m; Programmversion: 3.1; Text3: 0; Plugin_Bezeichnung: MainObject; Plugin_Objektname: SmartPartCompressed; Version: 1.1; Abstand_Öffn_Unten: 9.125 m; ash T_Feuchtebeständigkeit: nein; Feuerwiderstandsklasse~: nein
WV 1.1 | H2 Ebene +2 |  | 1213Sma0813717573 |  | VUK1 - Lichtleiste (ELT) | St | Trockenbauarbeiten | SmartPart | WV 1.1 |  |  |  | 3.75 |  |  |  |  | - | AllplanAttributes - Text1: WA2001; UK: 0 m; OK: 0 m; V6: 0 m; V7: 0 m; V8: 0 m; V9: 0; Länge: 1.2 m; Dicke: 0.025 m; Höhe: 0.15 m; Programmversion: 3.1; Text3: 0; Plugin_Bezeichnung: MainObject; Plugin_Objektname: SmartPartCompressed; Version: 1.1; Abstand_Öffn_Unten: 9.125 m; ash T_Feuchtebeständigkeit: nein; Feuerwiderstandsklasse~: nein
WV 1.1 | H2 Ebene +2 |  | 1213Sma0813717575 |  | VUK1 - Lichtleiste (ELT) | St | Trockenbauarbeiten | SmartPart | WV 1.1 |  |  |  | 3.75 |  |  |  |  | - | AllplanAttributes - Text1: WA2001; UK: 0 m; OK: 0 m; V6: 0 m; V7: 0 m; V8: 0 m; V9: 0; Länge: 1.2 m; Dicke: 0.025 m; Höhe: 0.15 m; Programmversion: 3.1; Text3: 0; Plugin_Bezeichnung: MainObject; Plugin_Objektname: SmartPartCompressed; Version: 1.1; Abstand_Öffn_Unten: 9.125 m; ash T_Feuchtebeständigkeit: nein; Feuerwiderstandsklasse~: nein
WV 1.1 | H2 Ebene +2 |  | 1213Sma0813717577 |  | VUK1 - Lichtleiste (ELT) | St | Trockenbauarbeiten | SmartPart | WV 1.1 |  |  |  | 3.75 |  |  |  |  | - | AllplanAttributes - Text1: WA2001; UK: 0 m; OK: 0 m; V6: 0 m; V7: 0 m; V8: 0 m; V9: 0; Länge: 1.2 m; Dicke: 0.025 m; Höhe: 0.15 m; Programmversion: 3.1; Text3: 0; Plugin_Bezeichnung: MainObject; Plugin_Objektname: SmartPartCompressed; Version: 1.1; Abstand_Öffn_Unten: 9.125 m; ash T_Feuchtebeständigkeit: nein; Feuerwiderstandsklasse~: nein
WV 1.1 | H2 Ebene +2 |  | 1213Sma0813717579 |  | VUK1 - Lichtleiste (ELT) | St | Trockenbauarbeiten | SmartPart | WV 1.1 |  |  |  | 3.75 |  |  |  |  | - | AllplanAttributes - Text1: WA2001; UK: 0 m; OK: 0 m; V6: 0 m; V7: 0 m; V8: 0 m; V9: 0; Länge: 1.2 m; Dicke: 0.025 m; Höhe: 0.15 m; Programmversion: 3.1; Text3: 0; Plugin_Bezeichnung: MainObject; Plugin_Objektname: SmartPartCompressed; Version: 1.1; Abstand_Öffn_Unten: 9.125 m; ash T_Feuchtebeständigkeit: nein; Feuerwiderstandsklasse~: nein
WV 1.1 | H2 Ebene +2 |  | 1213Sma0813717581 |  | VUK1 - Lichtleiste (ELT) | St | Trockenbauarbeiten | SmartPart | WV 1.1 |  |  |  | 3.75 |  |  |  |  | - | AllplanAttributes - Text1: WA2001; UK: 0 m; OK: 0 m; V6: 0 m; V7: 0 m; V8: 0 m; V9: 0; Länge: 1.2 m; Dicke: 0.025 m; Höhe: 0.15 m; Programmversion: 3.1; Text3: 0; Plugin_Bezeichnung: MainObject; Plugin_Objektname: SmartPartCompressed; Version: 1.1; Abstand_Öffn_Unten: 9.125 m; ash T_Feuchtebeständigkeit: nein; Feuerwiderstandsklasse~: nein
WV 1.1 | H2 Ebene +2 |  | 1213Sma0813717583 |  | VUK1 - Lichtleiste (ELT) | St | Trockenbauarbeiten | SmartPart | WV 1.1 |  |  |  | 3.75 |  |  |  |  | - | AllplanAttributes - Text1: WA2001; UK: 0 m; OK: 0 m; V6: 0 m; V7: 0 m; V8: 0 m; V9: 0; Länge: 1.2 m; Dicke: 0.025 m; Höhe: 0.15 m; Programmversion: 3.1; Text3: 0; Plugin_Bezeichnung: MainObject; Plugin_Objektname: SmartPartCompressed; Version: 1.1; Abstand_Öffn_Unten: 9.125 m; ash T_Feuchtebeständigkeit: nein; Feuerwiderstandsklasse~: nein
WV 1.1 | H2 Ebene +2 |  | 1213Sma0813716925 |  | VUK1 - Lichtleiste (ELT) | St | Trockenbauarbeiten | SmartPart | WV 1.1 |  |  |  | 3.75 |  |  |  |  | - | AllplanAttributes - Text1: WA2010; UK: 0 m; OK: 0 m; V6: 0 m; V7: 0 m; V8: 0 m; V9: 0; Länge: 1.2 m; Dicke: 0.025 m; Höhe: 0.15 m; Programmversion: 3.1; Text3: 0; Plugin_Bezeichnung: MainObject; Plugin_Objektname: SmartPartCompressed; Version: 1.1; Abstand_Öffn_Unten: 9.125 m; ash T_Feuchtebeständigkeit: nein; Feuerwiderstandsklasse~: nein
WV 1.1 | H2 Ebene +2 |  | 1213Sma0813716939 |  | VUK1 - Lichtleiste (ELT) | St | Trockenbauarbeiten | SmartPart | WV 1.1 |  |  |  | 3.75 |  |  |  |  | - | AllplanAttributes - Text1: WA2010; UK: 0 m; OK: 0 m; V6: 0 m; V7: 0 m; V8: 0 m; V9: 0; Länge: 1.2 m; Dicke: 0.025 m; Höhe: 0.15 m; Programmversion: 3.1; Text3: 0; Plugin_Bezeichnung: MainObject; Plugin_Objektname: SmartPartCompressed; Version: 1.1; Abstand_Öffn_Unten: 9.125 m; ash T_Feuchtebeständigkeit: nein; Feuerwiderstandsklasse~: nein
WV 1.1 | H2 Ebene +2 |  | 1213Sma0813717171 |  | VUK1 - Lichtleiste (ELT) | St | Trockenbauarbeiten | SmartPart | WV 1.1 |  |  |  | 3.75 |  |  |  |  | - | AllplanAttributes - Text1: WA2010; UK: 0 m; OK: 0 m; V6: 0 m; V7: 0 m; V8: 0 m; V9: 0; Länge: 1.2 m; Dicke: 0.025 m; Höhe: 0.15 m; Programmversion: 3.1; Text3: 0; Plugin_Bezeichnung: MainObject; Plugin_Objektname: SmartPartCompressed; Version: 1.1; Abstand_Öffn_Unten: 9.125 m; ash T_Feuchtebeständigkeit: nein; Feuerwiderstandsklasse~: nein
WV 1.1 | H2 Ebene +2 |  | 1213Sma0813717196 |  | VUK1 - Lichtleiste (ELT) | St | Trockenbauarbeiten | SmartPart | WV 1.1 |  |  |  | 3.75 |  |  |  |  | - | AllplanAttributes - Text1: WA2010; UK: 0 m; OK: 0 m; V6: 0 m; V7: 0 m; V8: 0 m; V9: 0; Länge: 1.2 m; Dicke: 0.025 m; Höhe: 0.15 m; Programmversion: 3.1; Text3: 0; Plugin_Bezeichnung: MainObject; Plugin_Objektname: SmartPartCompressed; Version: 1.1; Abstand_Öffn_Unten: 9.125 m; ash T_Feuchtebeständigkeit: nein; Feuerwiderstandsklasse~: nein
WV 1.1 | H2 Ebene +2 |  | 1213Sma0813717210 |  | VUK5 - Handlauf | St | Trockenbauarbeiten | SmartPart | WV 1.1 |  |  |  | 3.75 |  |  |  |  | - | AllplanAttributes - Text1: WA; UK: 0 m; OK: 0 m; V6: 0 m; V7: 0 m; V8: 0 m; V9: 0; Länge: 1.5 m; Dicke: 0.025 m; Höhe: 0.2 m; Programmversion: 3.1; Text3: 0; Plugin_Bezeichnung: MainObject; Plugin_Objektname: SmartPartCompressed; Version: 1.1; Abstand_Öffn_Unten: 8.4 m; ash T_Feuchtebeständigkeit: nein; Feuerwiderstandsklasse~: nein
WV 1.1 | H2 Ebene +2 |  | 1213Sma0813717224 |  | VUK5 - Handlauf | St | Trockenbauarbeiten | SmartPart | WV 1.1 |  |  |  | 3.75 |  |  |  |  | - | AllplanAttributes - Text1: WA; UK: 0 m; OK: 0 m; V6: 0 m; V7: 0 m; V8: 0 m; V9: 0; Länge: 1.5 m; Dicke: 0.025 m; Höhe: 0.2 m; Programmversion: 3.1; Text3: 0; Plugin_Bezeichnung: MainObject; Plugin_Objektname: SmartPartCompressed; Version: 1.1; Abstand_Öffn_Unten: 8.4 m; ash T_Feuchtebeständigkeit: nein; Feuerwiderstandsklasse~: nein
WV 1.1 | H2 Ebene +2 |  | 1213Sma0813717226 |  | VUK5 - Handlauf | St | Trockenbauarbeiten | SmartPart | WV 1.1 |  |  |  | 3.75 |  |  |  |  | - | AllplanAttributes - Text1: WA; UK: 0 m; OK: 0 m; V6: 0 m; V7: 0 m; V8: 0 m; V9: 0; Länge: 1.5 m; Dicke: 0.025 m; Höhe: 0.2 m; Programmversion: 3.1; Text3: 0; Plugin_Bezeichnung: MainObject; Plugin_Objektname: SmartPartCompressed; Version: 1.1; Abstand_Öffn_Unten: 8.4 m; ash T_Feuchtebeständigkeit: nein; Feuerwiderstandsklasse~: nein
WV 1.1 | H2 Ebene +2 |  | 1213Sma0813717239 |  | VUK5 - Handlauf | St | Trockenbauarbeiten | SmartPart | WV 1.1 |  |  |  | 3.75 |  |  |  |  | - | AllplanAttributes - Text1: WA; UK: 0 m; OK: 0 m; V6: 0 m; V7: 0 m; V8: 0 m; V9: 0; Länge: 1.5 m; Dicke: 0.025 m; Höhe: 0.2 m; Programmversion: 3.1; Text3: 0; Plugin_Bezeichnung: MainObject; Plugin_Objektname: SmartPartCompressed; Version: 1.1; Abstand_Öffn_Unten: 8.4 m; ash T_Feuchtebeständigkeit: nein; Feuerwiderstandsklasse~: nein
WV 1.1 | H2 Ebene +2 |  | 1213Sma0813716983 |  | VUK1 - Hängeschrank | St | Trockenbauarbeiten | SmartPart | WV 1.1 |  |  |  | 3.75 |  |  |  |  | - | AllplanAttributes - Text1: WA2020; UK: 0 m; OK: 0 m; V6: 0 m; V7: 0 m; V8: 0 m; V9: 0; Länge: 0.8 m; Dicke: 0.025 m; Höhe: 0.2 m; Programmversion: 3.1; Text3: 0; Plugin_Bezeichnung: MainObject; Plugin_Objektname: SmartPartCompressed; Version: 1.1; Abstand_Öffn_Unten: 9.5 m; ash T_Feuchtebeständigkeit: nein; Feuerwiderstandsklasse~: nein
WV 1.1 | H2 Ebene +2 |  | 1213Sma0813717795 |  | VUK1 - Feuerlöcher | St | Trockenbauarbeiten | SmartPart | WV 1.1 |  |  |  | 3.75 |  |  |  |  | - | AllplanAttributes - UK: 0 m; OK: 0 m; V6: 0 m; V7: 0 m; V8: 0 m; V9: 0; Länge: 0.3 m; Dicke: 0.025 m; Höhe: 0.7 m; Programmversion: 3.1; Text3: 0; Plugin_Bezeichnung: MainObject; Plugin_Objektname: SmartPartCompressed; Version: 1.1; Abstand_Öffn_Unten: 8.35 m; ash T_Feuchtebeständigkeit: nein; Feuerwiderstandsklasse~: nein
WV 1.1 | H2 Ebene +2 |  | 1213Sma0813717798 |  | VUK1 - Feuerlöcher | St | Trockenbauarbeiten | SmartPart | WV 1.1 |  |  |  | 3.75 |  |  |  |  | - | AllplanAttributes - UK: 0 m; OK: 0 m; V6: 0 m; V7: 0 m; V8: 0 m; V9: 0; Länge: 0.3 m; Dicke: 0.025 m; Höhe: 0.7 m; Programmversion: 3.1; Text3: 0; Plugin_Bezeichnung: MainObject; Plugin_Objektname: SmartPartCompressed; Version: 1.1; Abstand_Öffn_Unten: 8.35 m; ash T_Feuchtebeständigkeit: nein; Feuerwiderstandsklasse~: nein
WV 1.1 | H2 Ebene +2 |  | 1213Sma0813717812 |  | VUK1 - Feuerlöcher | St | Trockenbauarbeiten | SmartPart | WV 1.1 |  |  |  | 3.75 |  |  |  |  | - | AllplanAttributes - UK: 0 m; OK: 0 m; V6: 0 m; V7: 0 m; V8: 0 m; V9: 0; Länge: 0.3 m; Dicke: 0.025 m; Höhe: 0.7 m; Programmversion: 3.1; Text3: 0; Plugin_Bezeichnung: MainObject; Plugin_Objektname: SmartPartCompressed; Version: 1.1; Abstand_Öffn_Unten: 8.35 m; ash T_Feuchtebeständigkeit: nein; Feuerwiderstandsklasse~: nein
WV 1.1 | H2 Ebene +2 |  | 1213Sma0813717815 |  | VUK1 - Feuerlöcher | St | Trockenbauarbeiten | SmartPart | WV 1.1 |  |  |  | 3.75 |  |  |  |  | - | AllplanAttributes - UK: 0 m; OK: 0 m; V6: 0 m; V7: 0 m; V8: 0 m; V9: 0; Länge: 0.3 m; Dicke: 0.025 m; Höhe: 0.7 m; Programmversion: 3.1; Text3: 0; Plugin_Bezeichnung: MainObject; Plugin_Objektname: SmartPartCompressed; Version: 1.1; Abstand_Öffn_Unten: 8.35 m; ash T_Feuchtebeständigkeit: nein; Feuerwiderstandsklasse~: nein
WV 1.1 | H2 Ebene +2 |  | 1213Sma0813717821 |  | VUK1 - Feuerlöcher | St | Trockenbauarbeiten | SmartPart | WV 1.1 |  |  |  | 3.75 |  |  |  |  | - | AllplanAttributes - UK: 0 m; OK: 0 m; V6: 0 m; V7: 0 m; V8: 0 m; V9: 0; Länge: 0.3 m; Dicke: 0.025 m; Höhe: 0.7 m; Programmversion: 3.1; Text3: 0; Plugin_Bezeichnung: MainObject; Plugin_Objektname: SmartPartCompressed; Version: 1.1; Abstand_Öffn_Unten: 8.35 m; ash T_Feuchtebeständigkeit: nein; Feuerwiderstandsklasse~: nein
WV 1.1 | H2 Ebene +2 |  | 1213Sma0813717824 |  | VUK1 - Feuerlöcher | St | Trockenbauarbeiten | SmartPart | WV 1.1 |  |  |  | 3.75 |  |  |  |  | - | AllplanAttributes - UK: 0 m; OK: 0 m; V6: 0 m; V7: 0 m; V8: 0 m; V9: 0; Länge: 0.3 m; Dicke: 0.025 m; Höhe: 0.7 m; Programmversion: 3.1; Text3: 0; Plugin_Bezeichnung: MainObject; Plugin_Objektname: SmartPartCompressed; Version: 1.1; Abstand_Öffn_Unten: 8.35 m; ash T_Feuchtebeständigkeit: nein; Feuerwiderstandsklasse~: nein
WV 1.1 | H2 Ebene +2 |  | 1213Sma0813717838 |  | VUK1 - Feuerlöcher | St | Trockenbauarbeiten | SmartPart | WV 1.1 |  |  |  | 3.75 |  |  |  |  | - | AllplanAttributes - UK: 0 m; OK: 0 m; V6: 0 m; V7: 0 m; V8: 0 m; V9: 0; Länge: 0.3 m; Dicke: 0.025 m; Höhe: 0.7 m; Programmversion: 3.1; Text3: 0; Plugin_Bezeichnung: MainObject; Plugin_Objektname: SmartPartCompressed; Version: 1.1; Abstand_Öffn_Unten: 8.35 m; ash T_Feuchtebeständigkeit: nein; Feuerwiderstandsklasse~: nein
WV 1.1 | H2 Ebene +2 |  | 1213Sma0813716721 |  | VUK1 - Desinfektionsmittelspender | St | Trockenbauarbeiten | SmartPart | WV 1.1 |  |  |  | 3.75 |  |  |  |  | - | AllplanAttributes - Text1: WA2020; UK: 0 m; OK: 0 m; V6: 0 m; V7: 0 m; V8: 0 m; V9: 0; Länge: 0.2 m; Dicke: 0.025 m; Höhe: 0.3 m; Programmversion: 3.1; Text3: 0; Plugin_Bezeichnung: MainObject; Plugin_Objektname: SmartPartCompressed; Version: 1.1; Abstand_Öffn_Unten: 8.76 m; ash T_Feuchtebeständigkeit: nein; Feuerwiderstandsklasse~: nein
WV 1.1 | H2 Ebene +2 |  | 1213Sma0813716969 |  | VUK1 - Desinfektionsmittelspender | St | Trockenbauarbeiten | SmartPart | WV 1.1 |  |  |  | 3.75 |  |  |  |  | - | AllplanAttributes - Text1: WA2020; UK: 0 m; OK: 0 m; V6: 0 m; V7: 0 m; V8: 0 m; V9: 0; Länge: 0.2 m; Dicke: 0.025 m; Höhe: 0.3 m; Programmversion: 3.1; Text3: 0; Plugin_Bezeichnung: MainObject; Plugin_Objektname: SmartPartCompressed; Version: 1.1; Abstand_Öffn_Unten: 8.76 m; ash T_Feuchtebeständigkeit: nein; Feuerwiderstandsklasse~: nein
WV 1.1 | H2 Ebene +2 |  | 1213Sma0813717028 |  | VUK2 | St | Trockenbauarbeiten | SmartPart | WV 1.1 |  |  |  | 3.75 |  |  |  |  | - | AllplanAttributes - UK: 0 m; OK: 0 m; V6: 0 m; V7: 0 m; V8: 0 m; V9: 0; Länge: 2.92 m; Dicke: 0.018 m; Höhe: 0.3 m; Programmversion: 3.1; Text3: 0; Plugin_Bezeichnung: MainObject; Plugin_Objektname: SmartPartCompressed; Version: 1.1; Abstand_Öffn_Unten: 9.9 m; ash T_Feuchtebeständigkeit: nein; Feuerwiderstandsklasse~: nein
WV 1.1 | H2 Ebene +2 |  | 1213Sma0813718302 |  | VUK2 | St | Trockenbauarbeiten | SmartPart | WV 1.1 |  |  |  | 3.75 |  |  |  |  | - | AllplanAttributes - UK: 0 m; OK: 0 m; V6: 0 m; V7: 0 m; V8: 0 m; V9: 0; Länge: 2.92 m; Dicke: 0.018 m; Höhe: 0.3 m; Programmversion: 3.1; Text3: 0; Plugin_Bezeichnung: MainObject; Plugin_Objektname: SmartPartCompressed; Version: 1.1; Abstand_Öffn_Unten: 9.9 m; ash T_Feuchtebeständigkeit: nein; Feuerwiderstandsklasse~: nein
WV 1.1 | H2 Ebene +2 |  | 1213Sma0813717042 |  | VUK2 | St | Trockenbauarbeiten | SmartPart | WV 1.1 |  |  |  | 3.75 |  |  |  |  | - | AllplanAttributes - UK: 0 m; OK: 0 m; V6: 0 m; V7: 0 m; V8: 0 m; V9: 0; Länge: 2.92 m; Dicke: 0.018 m; Höhe: 0.3 m; Programmversion: 3.1; Text3: 0; Plugin_Bezeichnung: MainObject; Plugin_Objektname: SmartPartCompressed; Version: 1.1; Abstand_Öffn_Unten: 9.1 m; ash T_Feuchtebeständigkeit: nein; Feuerwiderstandsklasse~: nein
WV 1.1 | H2 Ebene +2 |  | 1213Sma0813718305 |  | VUK2 | St | Trockenbauarbeiten | SmartPart | WV 1.1 |  |  |  | 3.75 |  |  |  |  | - | AllplanAttributes - UK: 0 m; OK: 0 m; V6: 0 m; V7: 0 m; V8: 0 m; V9: 0; Länge: 2.92 m; Dicke: 0.018 m; Höhe: 0.3 m; Programmversion: 3.1; Text3: 0; Plugin_Bezeichnung: MainObject; Plugin_Objektname: SmartPartCompressed; Version: 1.1; Abstand_Öffn_Unten: 9.1 m; ash T_Feuchtebeständigkeit: nein; Feuerwiderstandsklasse~: nein
WV 1.1 | H2 Ebene +2 |  | 1213Sma0813716997 |  | VUK1 - Hängeschrank | St | Trockenbauarbeiten | SmartPart | WV 1.1 |  |  |  | 3.75 |  |  |  |  | - | AllplanAttributes - Text1: WA2012; UK: 0 m; OK: 0 m; V6: 0 m; V7: 0 m; V8: 0 m; V9: 0; Länge: 2.48 m; Dicke: 0.025 m; Höhe: 0.2 m; Programmversion: 3.1; Text3: 0; Plugin_Bezeichnung: MainObject; Plugin_Objektname: SmartPartCompressed; Version: 1.1; Abstand_Öffn_Unten: 9.85 m; ash T_Feuchtebeständigkeit: nein; Feuerwiderstandsklasse~: nein
WV 1.1 | H2 Ebene +2 |  | 1213Sma0813717852 |  | VUK2 | St | Trockenbauarbeiten | SmartPart | WV 1.1 |  |  |  | 3.75 |  |  |  |  | - | AllplanAttributes - UK: 0 m; OK: 0 m; V6: 0 m; V7: 0 m; V8: 0 m; V9: 0; Länge: 2.82 m; Dicke: 0.018 m; Höhe: 0.3 m; Programmversion: 3.1; Text3: 0; Plugin_Bezeichnung: MainObject; Plugin_Objektname: SmartPartCompressed; Version: 1.1; Abstand_Öffn_Unten: 9.9 m; ash T_Feuchtebeständigkeit: nein; Feuerwiderstandsklasse~: nein
WV 1.1 | H2 Ebene +2 |  | 1213Sma0813717996 |  | VUK2 | St | Trockenbauarbeiten | SmartPart | WV 1.1 |  |  |  | 3.75 |  |  |  |  | - | AllplanAttributes - UK: 0 m; OK: 0 m; V6: 0 m; V7: 0 m; V8: 0 m; V9: 0; Länge: 2.82 m; Dicke: 0.018 m; Höhe: 0.3 m; Programmversion: 3.1; Text3: 0; Plugin_Bezeichnung: MainObject; Plugin_Objektname: SmartPartCompressed; Version: 1.1; Abstand_Öffn_Unten: 9.9 m; ash T_Feuchtebeständigkeit: nein; Feuerwiderstandsklasse~: nein
WV 1.1 | H2 Ebene +2 |  | 1213Sma0813718023 |  | VUK2 | St | Trockenbauarbeiten | SmartPart | WV 1.1 |  |  |  | 3.75 |  |  |  |  | - | AllplanAttributes - UK: 0 m; OK: 0 m; V6: 0 m; V7: 0 m; V8: 0 m; V9: 0; Länge: 2.82 m; Dicke: 0.018 m; Höhe: 0.3 m; Programmversion: 3.1; Text3: 0; Plugin_Bezeichnung: MainObject; Plugin_Objektname: SmartPartCompressed; Version: 1.1; Abstand_Öffn_Unten: 9.9 m; ash T_Feuchtebeständigkeit: nein; Feuerwiderstandsklasse~: nein
WV 1.1 | H2 Ebene +2 |  | 1213Sma0813718050 |  | VUK2 | St | Trockenbauarbeiten | SmartPart | WV 1.1 |  |  |  | 3.75 |  |  |  |  | - | AllplanAttributes - UK: 0 m; OK: 0 m; V6: 0 m; V7: 0 m; V8: 0 m; V9: 0; Länge: 2.82 m; Dicke: 0.018 m; Höhe: 0.3 m; Programmversion: 3.1; Text3: 0; Plugin_Bezeichnung: MainObject; Plugin_Objektname: SmartPartCompressed; Version: 1.1; Abstand_Öffn_Unten: 9.9 m; ash T_Feuchtebeständigkeit: nein; Feuerwiderstandsklasse~: nein
WV 1.1 | H2 Ebene +2 |  | 1213Sma0813718077 |  | VUK2 | St | Trockenbauarbeiten | SmartPart | WV 1.1 |  |  |  | 3.75 |  |  |  |  | - | AllplanAttributes - UK: 0 m; OK: 0 m; V6: 0 m; V7: 0 m; V8: 0 m; V9: 0; Länge: 2.82 m; Dicke: 0.018 m; Höhe: 0.3 m; Programmversion: 3.1; Text3: 0; Plugin_Bezeichnung: MainObject; Plugin_Objektname: SmartPartCompressed; Version: 1.1; Abstand_Öffn_Unten: 9.9 m; ash T_Feuchtebeständigkeit: nein; Feuerwiderstandsklasse~: nein
WV 1.1 | H2 Ebene +2 |  | 1213Sma0813718081 |  | VUK2 | St | Trockenbauarbeiten | SmartPart | WV 1.1 |  |  |  | 3.75 |  |  |  |  | - | AllplanAttributes - UK: 0 m; OK: 0 m; V6: 0 m; V7: 0 m; V8: 0 m; V9: 0; Länge: 2.82 m; Dicke: 0.018 m; Höhe: 0.3 m; Programmversion: 3.1; Text3: 0; Plugin_Bezeichnung: MainObject; Plugin_Objektname: SmartPartCompressed; Version: 1.1; Abstand_Öffn_Unten: 9.9 m; ash T_Feuchtebeständigkeit: nein; Feuerwiderstandsklasse~: nein
WV 1.1 | H2 Ebene +2 |  | 1213Sma0813718085 |  | VUK2 | St | Trockenbauarbeiten | SmartPart | WV 1.1 |  |  |  | 3.75 |  |  |  |  | - | AllplanAttributes - UK: 0 m; OK: 0 m; V6: 0 m; V7: 0 m; V8: 0 m; V9: 0; Länge: 2.82 m; Dicke: 0.018 m; Höhe: 0.3 m; Programmversion: 3.1; Text3: 0; Plugin_Bezeichnung: MainObject; Plugin_Objektname: SmartPartCompressed; Version: 1.1; Abstand_Öffn_Unten: 9.9 m; ash T_Feuchtebeständigkeit: nein; Feuerwiderstandsklasse~: nein
WV 1.1 | H2 Ebene +2 |  | 1213Sma0813718089 |  | VUK2 | St | Trockenbauarbeiten | SmartPart | WV 1.1 |  |  |  | 3.75 |  |  |  |  | - | AllplanAttributes - UK: 0 m; OK: 0 m; V6: 0 m; V7: 0 m; V8: 0 m; V9: 0; Länge: 2.82 m; Dicke: 0.018 m; Höhe: 0.3 m; Programmversion: 3.1; Text3: 0; Plugin_Bezeichnung: MainObject; Plugin_Objektname: SmartPartCompressed; Version: 1.1; Abstand_Öffn_Unten: 9.9 m; ash T_Feuchtebeständigkeit: nein; Feuerwiderstandsklasse~: nein
WV 1.1 | H2 Ebene +2 |  | 1213Sma0813717855 |  | VUK2 | St | Trockenbauarbeiten | SmartPart | WV 1.1 |  |  |  | 3.75 |  |  |  |  | - | AllplanAttributes - UK: 0 m; OK: 0 m; V6: 0 m; V7: 0 m; V8: 0 m; V9: 0; Länge: 2.82 m; Dicke: 0.018 m; Höhe: 0.3 m; Programmversion: 3.1; Text3: 0; Plugin_Bezeichnung: MainObject; Plugin_Objektname: SmartPartCompressed; Version: 1.1; Abstand_Öffn_Unten: 9.1 m; ash T_Feuchtebeständigkeit: nein; Feuerwiderstandsklasse~: nein
WV 1.1 | H2 Ebene +2 |  | 1213Sma0813717998 |  | VUK2 | St | Trockenbauarbeiten | SmartPart | WV 1.1 |  |  |  | 3.75 |  |  |  |  | - | AllplanAttributes - UK: 0 m; OK: 0 m; V6: 0 m; V7: 0 m; V8: 0 m; V9: 0; Länge: 2.82 m; Dicke: 0.018 m; Höhe: 0.3 m; Programmversion: 3.1; Text3: 0; Plugin_Bezeichnung: MainObject; Plugin_Objektname: SmartPartCompressed; Version: 1.1; Abstand_Öffn_Unten: 9.1 m; ash T_Feuchtebeständigkeit: nein; Feuerwiderstandsklasse~: nein
WV 1.1 | H2 Ebene +2 |  | 1213Sma0813718025 |  | VUK2 | St | Trockenbauarbeiten | SmartPart | WV 1.1 |  |  |  | 3.75 |  |  |  |  | - | AllplanAttributes - UK: 0 m; OK: 0 m; V6: 0 m; V7: 0 m; V8: 0 m; V9: 0; Länge: 2.82 m; Dicke: 0.018 m; Höhe: 0.3 m; Programmversion: 3.1; Text3: 0; Plugin_Bezeichnung: MainObject; Plugin_Objektname: SmartPartCompressed; Version: 1.1; Abstand_Öffn_Unten: 9.1 m; ash T_Feuchtebeständigkeit: nein; Feuerwiderstandsklasse~: nein
WV 1.1 | H2 Ebene +2 |  | 1213Sma0813718052 |  | VUK2 | St | Trockenbauarbeiten | SmartPart | WV 1.1 |  |  |  | 3.75 |  |  |  |  | - | AllplanAttributes - UK: 0 m; OK: 0 m; V6: 0 m; V7: 0 m; V8: 0 m; V9: 0; Länge: 2.82 m; Dicke: 0.018 m; Höhe: 0.3 m; Programmversion: 3.1; Text3: 0; Plugin_Bezeichnung: MainObject; Plugin_Objektname: SmartPartCompressed; Version: 1.1; Abstand_Öffn_Unten: 9.1 m; ash T_Feuchtebeständigkeit: nein; Feuerwiderstandsklasse~: nein
WV 1.1 | H2 Ebene +2 |  | 1213Sma0813718079 |  | VUK2 | St | Trockenbauarbeiten | SmartPart | WV 1.1 |  |  |  | 3.75 |  |  |  |  | - | AllplanAttributes - UK: 0 m; OK: 0 m; V6: 0 m; V7: 0 m; V8: 0 m; V9: 0; Länge: 2.82 m; Dicke: 0.018 m; Höhe: 0.3 m; Programmversion: 3.1; Text3: 0; Plugin_Bezeichnung: MainObject; Plugin_Objektname: SmartPartCompressed; Version: 1.1; Abstand_Öffn_Unten: 9.1 m; ash T_Feuchtebeständigkeit: nein; Feuerwiderstandsklasse~: nein
WV 1.1 | H2 Ebene +2 |  | 1213Sma0813718083 |  | VUK2 | St | Trockenbauarbeiten | SmartPart | WV 1.1 |  |  |  | 3.75 |  |  |  |  | - | AllplanAttributes - UK: 0 m; OK: 0 m; V6: 0 m; V7: 0 m; V8: 0 m; V9: 0; Länge: 2.82 m; Dicke: 0.018 m; Höhe: 0.3 m; Programmversion: 3.1; Text3: 0; Plugin_Bezeichnung: MainObject; Plugin_Objektname: SmartPartCompressed; Version: 1.1; Abstand_Öffn_Unten: 9.1 m; ash T_Feuchtebeständigkeit: nein; Feuerwiderstandsklasse~: nein
WV 1.1 | H2 Ebene +2 |  | 1213Sma0813718087 |  | VUK2 | St | Trockenbauarbeiten | SmartPart | WV 1.1 |  |  |  | 3.75 |  |  |  |  | - | AllplanAttributes - UK: 0 m; OK: 0 m; V6: 0 m; V7: 0 m; V8: 0 m; V9: 0; Länge: 2.82 m; Dicke: 0.018 m; Höhe: 0.3 m; Programmversion: 3.1; Text3: 0; Plugin_Bezeichnung: MainObject; Plugin_Objektname: SmartPartCompressed; Version: 1.1; Abstand_Öffn_Unten: 9.1 m; ash T_Feuchtebeständigkeit: nein; Feuerwiderstandsklasse~: nein
WV 1.1 | H2 Ebene +2 |  | 1213Sma0813718091 |  | VUK2 | St | Trockenbauarbeiten | SmartPart | WV 1.1 |  |  |  | 3.75 |  |  |  |  | - | AllplanAttributes - UK: 0 m; OK: 0 m; V6: 0 m; V7: 0 m; V8: 0 m; V9: 0; Länge: 2.82 m; Dicke: 0.018 m; Höhe: 0.3 m; Programmversion: 3.1; Text3: 0; Plugin_Bezeichnung: MainObject; Plugin_Objektname: SmartPartCompressed; Version: 1.1; Abstand_Öffn_Unten: 9.1 m; ash T_Feuchtebeständigkeit: nein; Feuerwiderstandsklasse~: nein
WV 1.1 | H2 Ebene +2 |  | 1213Sma0813717881 |  | VUK2 | St | Trockenbauarbeiten | SmartPart | WV 1.1 |  |  |  | 3.75 |  |  |  |  | - | AllplanAttributes - UK: 0 m; OK: 0 m; V6: 0 m; V7: 0 m; V8: 0 m; V9: 0; Länge: 0.35 m; Dicke: 0.018 m; Höhe: 0.3 m; Programmversion: 3.1; Text3: 0; Plugin_Bezeichnung: MainObject; Plugin_Objektname: SmartPartCompressed; Version: 1.1; Abstand_Öffn_Unten: 9.9 m; ash T_Feuchtebeständigkeit: nein; Feuerwiderstandsklasse~: nein
WV 1.1 | H2 Ebene +2 |  | 1213Sma0813717884 |  | VUK2 | St | Trockenbauarbeiten | SmartPart | WV 1.1 |  |  |  | 3.75 |  |  |  |  | - | AllplanAttributes - UK: 0 m; OK: 0 m; V6: 0 m; V7: 0 m; V8: 0 m; V9: 0; Länge: 0.35 m; Dicke: 0.018 m; Höhe: 0.3 m; Programmversion: 3.1; Text3: 0; Plugin_Bezeichnung: MainObject; Plugin_Objektname: SmartPartCompressed; Version: 1.1; Abstand_Öffn_Unten: 9.1 m; ash T_Feuchtebeständigkeit: nein; Feuerwiderstandsklasse~: nein
WV 1.1 | H2 Ebene +2 |  | 1213Sma0813717968 |  | VUK2 | St | Trockenbauarbeiten | SmartPart | WV 1.1 |  |  |  | 3.75 |  |  |  |  | - | AllplanAttributes - UK: 0 m; OK: 0 m; V6: 0 m; V7: 0 m; V8: 0 m; V9: 0; Länge: 0.74 m; Dicke: 0.018 m; Höhe: 0.3 m; Programmversion: 3.1; Text3: 0; Plugin_Bezeichnung: MainObject; Plugin_Objektname: SmartPartCompressed; Version: 1.1; Abstand_Öffn_Unten: 9.9 m; ash T_Feuchtebeständigkeit: nein; Feuerwiderstandsklasse~: nein
WV 1.1 | H2 Ebene +2 |  | 1213Sma0813717938 |  | VUK2 | St | Trockenbauarbeiten | SmartPart | WV 1.1 |  |  |  | 3.75 |  |  |  |  | - | AllplanAttributes - UK: 0 m; OK: 0 m; V6: 0 m; V7: 0 m; V8: 0 m; V9: 0; Länge: 0.5 m; Dicke: 0.018 m; Höhe: 0.3 m; Programmversion: 3.1; Text3: 0; Plugin_Bezeichnung: MainObject; Plugin_Objektname: SmartPartCompressed; Version: 1.1; Abstand_Öffn_Unten: 9.9 m; ash T_Feuchtebeständigkeit: nein; Feuerwiderstandsklasse~: nein
WV 1.1 | H2 Ebene +2 |  | 1213Sma0813717941 |  | VUK2 | St | Trockenbauarbeiten | SmartPart | WV 1.1 |  |  |  | 3.75 |  |  |  |  | - | AllplanAttributes - UK: 0 m; OK: 0 m; V6: 0 m; V7: 0 m; V8: 0 m; V9: 0; Länge: 0.5 m; Dicke: 0.018 m; Höhe: 0.3 m; Programmversion: 3.1; Text3: 0; Plugin_Bezeichnung: MainObject; Plugin_Objektname: SmartPartCompressed; Version: 1.1; Abstand_Öffn_Unten: 9.1 m; ash T_Feuchtebeständigkeit: nein; Feuerwiderstandsklasse~: nein
WV 1.1 | H2 Ebene +2 |  | 1213Sma0813717910 |  | VUK2 | St | Trockenbauarbeiten | SmartPart | WV 1.1 |  |  |  | 3.75 |  |  |  |  | - | AllplanAttributes - UK: 0 m; OK: 0 m; V6: 0 m; V7: 0 m; V8: 0 m; V9: 0; Länge: 0.59 m; Dicke: 0.018 m; Höhe: 0.3 m; Programmversion: 3.1; Text3: 0; Plugin_Bezeichnung: MainObject; Plugin_Objektname: SmartPartCompressed; Version: 1.1; Abstand_Öffn_Unten: 9.9 m; ash T_Feuchtebeständigkeit: nein; Feuerwiderstandsklasse~: nein
WV 1.1 | H2 Ebene +2 |  | 1213Sma0813717971 |  | VUK2 | St | Trockenbauarbeiten | SmartPart | WV 1.1 |  |  |  | 3.75 |  |  |  |  | - | AllplanAttributes - UK: 0 m; OK: 0 m; V6: 0 m; V7: 0 m; V8: 0 m; V9: 0; Länge: 0.74 m; Dicke: 0.018 m; Höhe: 0.3 m; Programmversion: 3.1; Text3: 0; Plugin_Bezeichnung: MainObject; Plugin_Objektname: SmartPartCompressed; Version: 1.1; Abstand_Öffn_Unten: 9.1 m; ash T_Feuchtebeständigkeit: nein; Feuerwiderstandsklasse~: nein
WV 1.1 | H2 Ebene +2 |  | 1213Sma0813717924 |  | VUK2 | St | Trockenbauarbeiten | SmartPart | WV 1.1 |  |  |  | 3.75 |  |  |  |  | - | AllplanAttributes - UK: 0 m; OK: 0 m; V6: 0 m; V7: 0 m; V8: 0 m; V9: 0; Länge: 0.59 m; Dicke: 0.018 m; Höhe: 0.3 m; Programmversion: 3.1; Text3: 0; Plugin_Bezeichnung: MainObject; Plugin_Objektname: SmartPartCompressed; Version: 1.1; Abstand_Öffn_Unten: 9.1 m; ash T_Feuchtebeständigkeit: nein; Feuerwiderstandsklasse~: nein
WV 1.1 | H2 Ebene +2 |  | 1213Sma0813717012 |  | VUK5 - Handlauf | St | Trockenbauarbeiten | SmartPart | WV 1.1 |  |  |  | 3.75 |  |  |  |  | - | AllplanAttributes - Text1: WA; UK: 0 m; OK: 0 m; V6: 0 m; V7: 0 m; V8: 0 m; V9: 0; Länge: 5.5 m; Dicke: 0.025 m; Höhe: 0.2 m; Programmversion: 3.1; Text3: 0; Plugin_Bezeichnung: MainObject; Plugin_Objektname: SmartPartCompressed; Version: 1.1; Abstand_Öffn_Unten: 8.4 m; ash T_Feuchtebeständigkeit: nein; Feuerwiderstandsklasse~: nein
WV 1.1 | H2 Ebene +2 |  | 1213Sma0813718336 |  | VUK1 - Desinfektionsmittelspender | St | Trockenbauarbeiten | SmartPart | WV 1.1 |  |  |  | 3.75 |  |  |  |  | - | AllplanAttributes - Text1: WA2018; UK: 0 m; OK: 0 m; V6: 0 m; V7: 0 m; V8: 0 m; V9: 0; Länge: 1.21 m; Dicke: 0.025 m; Höhe: 0.25 m; Programmversion: 3.1; Text3: 0; Plugin_Bezeichnung: MainObject; Plugin_Objektname: SmartPartCompressed; Version: 1.1; Abstand_Öffn_Unten: 7.5 m; ash T_Feuchtebeständigkeit: nein; Feuerwiderstandsklasse~: nein
WV 1.1 | H2 Ebene +2 |  | 1213Sma0813718349 |  | VUK1 - Desinfektionsmittelspender | St | Trockenbauarbeiten | SmartPart | WV 1.1 |  |  |  | 3.75 |  |  |  |  | - | AllplanAttributes - Text1: WA2018; UK: 0 m; OK: 0 m; V6: 0 m; V7: 0 m; V8: 0 m; V9: 0; Länge: 1.21 m; Dicke: 0.025 m; Höhe: 0.25 m; Programmversion: 3.1; Text3: 0; Plugin_Bezeichnung: MainObject; Plugin_Objektname: SmartPartCompressed; Version: 1.1; Abstand_Öffn_Unten: 7.5 m; ash T_Feuchtebeständigkeit: nein; Feuerwiderstandsklasse~: nein
WV 1.1 | H2 Ebene +2 |  | 1213Sma0813718413 |  | VUK1 - Desinfektionsmittelspender | St | Trockenbauarbeiten | SmartPart | WV 1.1 |  |  |  | 3.75 |  |  |  |  | - | AllplanAttributes - Text1: WA2018; UK: 0 m; OK: 0 m; V6: 0 m; V7: 0 m; V8: 0 m; V9: 0; Länge: 3.79 m; Dicke: 0.025 m; Höhe: 0.25 m; Programmversion: 3.1; Text3: 0; Plugin_Bezeichnung: MainObject; Plugin_Objektname: SmartPartCompressed; Version: 1.1; Abstand_Öffn_Unten: 7.5 m; ash T_Feuchtebeständigkeit: nein; Feuerwiderstandsklasse~: nein
WV 1.1 | H2 Ebene +2 |  | 1213Sma0813717264 |  | VUK1 - Monitor | St | Trockenbauarbeiten | SmartPart | WV 1.1 |  |  |  | 3.75 |  |  |  |  | - | AllplanAttributes - Text1: WA2030; UK: 0 m; OK: 0 m; V6: 0 m; V7: 0 m; V8: 0 m; V9: 0; Länge: 1.2 m; Dicke: 0.025 m; Höhe: 1 m; Programmversion: 3.1; Text3: 0; Plugin_Bezeichnung: MainObject; Plugin_Objektname: SmartPartCompressed; Version: 1.1; Abstand_Öffn_Unten: 8.6 m; ash T_Feuchtebeständigkeit: nein; Feuerwiderstandsklasse~: nein
WV 1.1 | H2 Ebene +2 |  | 1213Sma0813716644 |  | VUK1 - Desinfektionsmittelspender | St | Trockenbauarbeiten | SmartPart | WV 1.1 |  |  |  | 3.75 |  |  |  |  | - | AllplanAttributes - Text1: WA2018; UK: 0 m; OK: 0 m; V6: 0 m; V7: 0 m; V8: 0 m; V9: 0; Länge: 0.2 m; Dicke: 0.025 m; Höhe: 0.3 m; Programmversion: 3.1; Text3: 0; Plugin_Bezeichnung: MainObject; Plugin_Objektname: SmartPartCompressed; Version: 1.1; Abstand_Öffn_Unten: 8.76 m; ash T_Feuchtebeständigkeit: nein; Feuerwiderstandsklasse~: nein
WV 1.1 | H2 Ebene +2 |  | 1213Sma0813716690 |  | VUK1 - Desinfektionsmittelspender | St | Trockenbauarbeiten | SmartPart | WV 1.1 |  |  |  | 3.75 |  |  |  |  | - | AllplanAttributes - Text1: WA2018; UK: 0 m; OK: 0 m; V6: 0 m; V7: 0 m; V8: 0 m; V9: 0; Länge: 0.2 m; Dicke: 0.025 m; Höhe: 0.3 m; Programmversion: 3.1; Text3: 0; Plugin_Bezeichnung: MainObject; Plugin_Objektname: SmartPartCompressed; Version: 1.1; Abstand_Öffn_Unten: 8.76 m; ash T_Feuchtebeständigkeit: nein; Feuerwiderstandsklasse~: nein
WV 1.1 | H2 Ebene +2 |  | 1213Sma0813716641 |  | VUK1 - Hängeschrank | St | Trockenbauarbeiten | SmartPart | WV 1.1 |  |  |  | 3.75 |  |  |  |  | - | AllplanAttributes - Text1: WA2018; UK: 0 m; OK: 0 m; V6: 0 m; V7: 0 m; V8: 0 m; V9: 0; Länge: 3.76 m; Dicke: 0.025 m; Höhe: 0.2 m; Programmversion: 3.1; Text3: 0; Plugin_Bezeichnung: MainObject; Plugin_Objektname: SmartPartCompressed; Version: 1.1; Abstand_Öffn_Unten: 9.85 m; ash T_Feuchtebeständigkeit: nein; Feuerwiderstandsklasse~: nein
WV 1.1 | H2 Ebene +2 |  | 1213Sma0813718545 |  | VUK1 - Hängeschrank | St | Trockenbauarbeiten | SmartPart | WV 1.1 |  |  |  | 3.75 |  |  |  |  | - | AllplanAttributes - Text1: WA2018; UK: 0 m; OK: 0 m; V6: 0 m; V7: 0 m; V8: 0 m; V9: 0; Länge: 1.5 m; Dicke: 0.025 m; Höhe: 0.2 m; Programmversion: 3.1; Text3: 0; Plugin_Bezeichnung: MainObject; Plugin_Objektname: SmartPartCompressed; Version: 1.1; Abstand_Öffn_Unten: 9.85 m; ash T_Feuchtebeständigkeit: nein; Feuerwiderstandsklasse~: nein
WV 1.1 | H2 Ebene +2 |  | 1213Sma0813718756 |  | VUK1 - Hängeschrank | St | Trockenbauarbeiten | SmartPart | WV 1.1 |  |  |  | 3.75 |  |  |  |  | - | AllplanAttributes - Text1: WA2018; UK: 0 m; OK: 0 m; V6: 0 m; V7: 0 m; V8: 0 m; V9: 0; Länge: 1.5 m; Dicke: 0.025 m; Höhe: 0.2 m; Programmversion: 3.1; Text3: 0; Plugin_Bezeichnung: MainObject; Plugin_Objektname: SmartPartCompressed; Version: 1.1; Abstand_Öffn_Unten: 9.85 m; ash T_Feuchtebeständigkeit: nein; Feuerwiderstandsklasse~: nein
WV 1.1 | H2 Ebene +2 |  | 1213Sma0813718559 |  | VUK1 - Seifenspender | St | Trockenbauarbeiten | SmartPart | WV 1.1 |  |  |  | 3.75 |  |  |  |  | - | AllplanAttributes - Text1: WA2016; UK: 0 m; OK: 0 m; V6: 0 m; V7: 0 m; V8: 0 m; V9: 0; Länge: 0.15 m; Dicke: 0.025 m; Höhe: 0.3 m; Programmversion: 3.1; Text3: 0; Plugin_Bezeichnung: MainObject; Plugin_Objektname: SmartPartCompressed; Version: 1.1; Abstand_Öffn_Unten: 8.76 m; ash T_Feuchtebeständigkeit: nein; Feuerwiderstandsklasse~: nein
WV 1.1 | H2 Ebene +2 |  | 1213Sma0813716659 |  | VUK1 - Desinfektionsmittelspender | St | Trockenbauarbeiten | SmartPart | WV 1.1 |  |  |  | 3.75 |  |  |  |  | - | AllplanAttributes - Text1: WA2016; UK: 0 m; OK: 0 m; V6: 0 m; V7: 0 m; V8: 0 m; V9: 0; Länge: 0.2 m; Dicke: 0.025 m; Höhe: 0.3 m; Programmversion: 3.1; Text3: 0; Plugin_Bezeichnung: MainObject; Plugin_Objektname: SmartPartCompressed; Version: 1.1; Abstand_Öffn_Unten: 8.76 m; ash T_Feuchtebeständigkeit: nein; Feuerwiderstandsklasse~: nein
WV 1.1 | H2 Ebene +2 |  | 1213Sma0813718785 |  | VUK1 - Desinfektionsmittelspender | St | Trockenbauarbeiten | SmartPart | WV 1.1 |  |  |  | 3.75 |  |  |  |  | - | AllplanAttributes - Text1: WA2016; UK: 0 m; OK: 0 m; V6: 0 m; V7: 0 m; V8: 0 m; V9: 0; Länge: 0.2 m; Dicke: 0.025 m; Höhe: 0.3 m; Programmversion: 3.1; Text3: 0; Plugin_Bezeichnung: MainObject; Plugin_Objektname: SmartPartCompressed; Version: 1.1; Abstand_Öffn_Unten: 8.76 m; ash T_Feuchtebeständigkeit: nein; Feuerwiderstandsklasse~: nein
WV 1.1 | H2 Ebene +2 |  | 1213Sma0813717278 |  | VUK1 - Haltegriff | St | Trockenbauarbeiten | SmartPart | WV 1.1 |  |  |  | 3.75 |  |  |  |  | - | AllplanAttributes - Text1: WA2018; UK: 0 m; OK: 0 m; V6: 0 m; V7: 0 m; V8: 0 m; V9: 0; Länge: 1.6 m; Dicke: 0.025 m; Höhe: 0.2 m; Programmversion: 3.1; Text3: 0; Plugin_Bezeichnung: MainObject; Plugin_Objektname: SmartPartCompressed; Version: 1.1; Abstand_Öffn_Unten: 9.05 m; ash T_Feuchtebeständigkeit: nein; Feuerwiderstandsklasse~: nein
WV 1.1 | H2 Ebene +2 |  | 1213Sma0813717742 |  | VUK1 - Desinfektionsmittelspender | St | Trockenbauarbeiten | SmartPart | WV 1.1 |  |  |  | 3.75 |  |  |  |  | - | AllplanAttributes - Text1: WA2020; UK: 0 m; OK: 0 m; V6: 0 m; V7: 0 m; V8: 0 m; V9: 0; Länge: 0.3 m; Dicke: 0.025 m; Höhe: 0.7 m; Programmversion: 3.1; Text3: 0; Plugin_Bezeichnung: MainObject; Plugin_Objektname: SmartPartCompressed; Version: 1.1; Abstand_Öffn_Unten: 8.35 m; ash T_Feuchtebeständigkeit: nein; Feuerwiderstandsklasse~: nein
WV 1.1 | H2 Ebene +2 |  | 1213Sma0813717756 |  | VUK1 - Desinfektionsmittelspender | St | Trockenbauarbeiten | SmartPart | WV 1.1 |  |  |  | 3.75 |  |  |  |  | - | AllplanAttributes - Text1: WA2020; UK: 0 m; OK: 0 m; V6: 0 m; V7: 0 m; V8: 0 m; V9: 0; Länge: 0.3 m; Dicke: 0.025 m; Höhe: 0.7 m; Programmversion: 3.1; Text3: 0; Plugin_Bezeichnung: MainObject; Plugin_Objektname: SmartPartCompressed; Version: 1.1; Abstand_Öffn_Unten: 8.35 m; ash T_Feuchtebeständigkeit: nein; Feuerwiderstandsklasse~: nein
WV 1.1 | H2 Ebene +2 |  | 1213Sma0813716605 |  | VUK1 - Hängeschrank | St | Trockenbauarbeiten | SmartPart | WV 1.1 |  |  |  | 3.75 |  |  |  |  | - | AllplanAttributes - Text1: WA2008; UK: 0 m; OK: 0 m; V6: 0 m; V7: 0 m; V8: 0 m; V9: 0; Länge: 2.2 m; Dicke: 0.025 m; Höhe: 0.2 m; Programmversion: 3.1; Text3: 0; Plugin_Bezeichnung: MainObject; Plugin_Objektname: SmartPartCompressed; Version: 1.1; Abstand_Öffn_Unten: 9.85 m; ash T_Feuchtebeständigkeit: nein; Feuerwiderstandsklasse~: nein
WV 1.1 | H2 Ebene +2 |  | 1213Sma0813716622 |  | VUK1 - Hängeschrank | St | Trockenbauarbeiten | SmartPart | WV 1.1 |  |  |  | 3.75 |  |  |  |  | - | AllplanAttributes - Text1: WA2008; UK: 0 m; OK: 0 m; V6: 0 m; V7: 0 m; V8: 0 m; V9: 0; Länge: 2.2 m; Dicke: 0.025 m; Höhe: 0.2 m; Programmversion: 3.1; Text3: 0; Plugin_Bezeichnung: MainObject; Plugin_Objektname: SmartPartCompressed; Version: 1.1; Abstand_Öffn_Unten: 9.85 m; ash T_Feuchtebeständigkeit: nein; Feuerwiderstandsklasse~: nein
WV 1.1 | H2 Ebene +2 |  | 1213Sma0813716620 |  | VUK1 - Hängeschrank | St | Trockenbauarbeiten | SmartPart | WV 1.1 |  |  |  | 3.75 |  |  |  |  | - | AllplanAttributes - Text1: WA2008; UK: 0 m; OK: 0 m; V6: 0 m; V7: 0 m; V8: 0 m; V9: 0; Länge: 4.65 m; Dicke: 0.025 m; Höhe: 0.2 m; Programmversion: 3.1; Text3: 0; Plugin_Bezeichnung: MainObject; Plugin_Objektname: SmartPartCompressed; Version: 1.1; Abstand_Öffn_Unten: 9.85 m; ash T_Feuchtebeständigkeit: nein; Feuerwiderstandsklasse~: nein
WV 1.1 | H2 Ebene +2 |  | 1213Sma0813717771 |  | VUK1 - Hängeschrank | St | Trockenbauarbeiten | SmartPart | WV 1.1 |  |  |  | 3.75 |  |  |  |  | - | AllplanAttributes - Text1: WA2008; UK: 0 m; OK: 0 m; V6: 0 m; V7: 0 m; V8: 0 m; V9: 0; Länge: 4.65 m; Dicke: 0.025 m; Höhe: 0.2 m; Programmversion: 3.1; Text3: 0; Plugin_Bezeichnung: MainObject; Plugin_Objektname: SmartPartCompressed; Version: 1.1; Abstand_Öffn_Unten: 9.85 m; ash T_Feuchtebeständigkeit: nein; Feuerwiderstandsklasse~: nein
WV 1.1 | H2 Ebene +2 |  | 1213Sma0813717792 |  | VUK1 - Feuerlöscher | St | Trockenbauarbeiten | SmartPart | WV 1.1 |  |  |  | 3.75 |  |  |  |  | - | AllplanAttributes - UK: 0 m; OK: 0 m; V6: 0 m; V7: 0 m; V8: 0 m; V9: 0; Länge: 0.3 m; Dicke: 0.025 m; Höhe: 0.7 m; Programmversion: 3.1; Text3: 0; Plugin_Bezeichnung: MainObject; Plugin_Objektname: SmartPartCompressed; Version: 1.1; Abstand_Öffn_Unten: 8.35 m; ash T_Feuchtebeständigkeit: nein; Feuerwiderstandsklasse~: nein
WV 1.1 | H2 Ebene +2 |  | 1213Sma0813717818 |  | VUK1 - Feuerlöscher | St | Trockenbauarbeiten | SmartPart | WV 1.1 |  |  |  | 3.75 |  |  |  |  | - | AllplanAttributes - UK: 0 m; OK: 0 m; V6: 0 m; V7: 0 m; V8: 0 m; V9: 0; Länge: 0.3 m; Dicke: 0.025 m; Höhe: 0.7 m; Programmversion: 3.1; Text3: 0; Plugin_Bezeichnung: MainObject; Plugin_Objektname: SmartPartCompressed; Version: 1.1; Abstand_Öffn_Unten: 8.35 m; ash T_Feuchtebeständigkeit: nein; Feuerwiderstandsklasse~: nein
WV 1.1 | H2 Ebene +2 |  | 1213Sma0813718479 |  | VUK1 | St | Trockenbauarbeiten | SmartPart | WV 1.1 |  |  |  | 3.75 |  |  |  |  | - | AllplanAttributes - UK: 0 m; OK: 0 m; V6: 0 m; V7: 0 m; V8: 0 m; V9: 0; Länge: 0.6 m; Dicke: 0.025 m; Höhe: 0.35 m; Programmversion: 3.1; Text3: 0; Plugin_Bezeichnung: MainObject; Plugin_Objektname: SmartPartCompressed; Version: 1.1; Abstand_Öffn_Unten: 8.75 m; ash T_Feuchtebeständigkeit: nein; Feuerwiderstandsklasse~: nein
WV 1.1 | H2 Ebene +2 |  | 1213Sma0813717789 |  | VUK1 | St | Trockenbauarbeiten | SmartPart | WV 1.1 |  |  |  | 3.75 |  |  |  |  | - | AllplanAttributes - UK: 0 m; OK: 0 m; V6: 0 m; V7: 0 m; V8: 0 m; V9: 0; Länge: 0.2 m; Dicke: 0.025 m; Höhe: 0.4 m; Programmversion: 3.1; Text3: 0; Plugin_Bezeichnung: MainObject; Plugin_Objektname: SmartPartCompressed; Version: 1.1; Abstand_Öffn_Unten: 8.13 m; ash T_Feuchtebeständigkeit: nein; Feuerwiderstandsklasse~: nein
WV 1.1 | H2 Ebene +2 |  | 1213Sma0813718450 |  | VUK1 | St | Trockenbauarbeiten | SmartPart | WV 1.1 |  |  |  | 3.75 |  |  |  |  | - | AllplanAttributes - UK: 0 m; OK: 0 m; V6: 0 m; V7: 0 m; V8: 0 m; V9: 0; Länge: 0.2 m; Dicke: 0.025 m; Höhe: 0.4 m; Programmversion: 3.1; Text3: 0; Plugin_Bezeichnung: MainObject; Plugin_Objektname: SmartPartCompressed; Version: 1.1; Abstand_Öffn_Unten: 8.13 m; ash T_Feuchtebeständigkeit: nein; Feuerwiderstandsklasse~: nein
WV 1.1 | H2 Ebene +2 |  | 1213Sma0813718465 |  | VUK1 | St | Trockenbauarbeiten | SmartPart | WV 1.1 |  |  |  | 3.75 |  |  |  |  | - | AllplanAttributes - UK: 0 m; OK: 0 m; V6: 0 m; V7: 0 m; V8: 0 m; V9: 0; Länge: 0.2 m; Dicke: 0.025 m; Höhe: 0.4 m; Programmversion: 3.1; Text3: 0; Plugin_Bezeichnung: MainObject; Plugin_Objektname: SmartPartCompressed; Version: 1.1; Abstand_Öffn_Unten: 8.13 m; ash T_Feuchtebeständigkeit: nein; Feuerwiderstandsklasse~: nein
WV 1.1 | H2 Ebene +2 |  | 1213Sma0813718492 |  | VUK1 | St | Trockenbauarbeiten | SmartPart | WV 1.1 |  |  |  | 3.75 |  |  |  |  | - | AllplanAttributes - UK: 0 m; OK: 0 m; V6: 0 m; V7: 0 m; V8: 0 m; V9: 0; Länge: 0.2 m; Dicke: 0.025 m; Höhe: 0.4 m; Programmversion: 3.1; Text3: 0; Plugin_Bezeichnung: MainObject; Plugin_Objektname: SmartPartCompressed; Version: 1.1; Abstand_Öffn_Unten: 8.13 m; ash T_Feuchtebeständigkeit: nein; Feuerwiderstandsklasse~: nein
WV 1.1 | H2 Ebene +2 |  | 1213Sma0813716704 |  | VUK1 - Hängeschrank | St | Trockenbauarbeiten | SmartPart | WV 1.1 |  |  |  | 3.75 |  |  |  |  | - | AllplanAttributes - Text1: WA2018; UK: 0 m; OK: 0 m; V6: 0 m; V7: 0 m; V8: 0 m; V9: 0; Länge: 5.74 m; Dicke: 0.025 m; Höhe: 0.2 m; Programmversion: 3.1; Text3: 0; Plugin_Bezeichnung: MainObject; Plugin_Objektname: SmartPartCompressed; Version: 1.1; Abstand_Öffn_Unten: 9.85 m; ash T_Feuchtebeständigkeit: nein; Feuerwiderstandsklasse~: nein
WV 1.1 | H2 Ebene +2 |  | 1213Sma0813716676 |  | VUK1 - Haltegriff | St | Trockenbauarbeiten | SmartPart | WV 1.1 |  |  |  | 3.75 |  |  |  |  | - | AllplanAttributes - Text1: WA2018; UK: 0 m; OK: 0 m; V6: 0 m; V7: 0 m; V8: 0 m; V9: 0; Länge: 1.6 m; Dicke: 0.025 m; Höhe: 0.2 m; Programmversion: 3.1; Text3: 0; Plugin_Bezeichnung: MainObject; Plugin_Objektname: SmartPartCompressed; Version: 1.1; Abstand_Öffn_Unten: 9.05 m; ash T_Feuchtebeständigkeit: nein; Feuerwiderstandsklasse~: nein
WV 1.1 | H2 Ebene +2 |  | 1213Sma0813718759 |  | VUK1 - Seifenspender | St | Trockenbauarbeiten | SmartPart | WV 1.1 |  |  |  | 3.75 |  |  |  |  | - | AllplanAttributes - Text1: WA2016; UK: 0 m; OK: 0 m; V6: 0 m; V7: 0 m; V8: 0 m; V9: 0; Länge: 0.2 m; Dicke: 0.025 m; Höhe: 0.3 m; Programmversion: 3.1; Text3: 0; Plugin_Bezeichnung: MainObject; Plugin_Objektname: SmartPartCompressed; Version: 1.1; Abstand_Öffn_Unten: 8.76 m; ash T_Feuchtebeständigkeit: nein; Feuerwiderstandsklasse~: nein
WV 1.1 | H2 Ebene +2 |  | 1213Sma0813718654 |  | VUK1 - Hängeschrank | St | Trockenbauarbeiten | SmartPart | WV 1.1 |  |  |  | 3.75 |  |  |  |  | - | AllplanAttributes - Text1: WA2009; UK: 0 m; OK: 0 m; V6: 0 m; V7: 0 m; V8: 0 m; V9: 0; Länge: 1.25 m; Dicke: 0.025 m; Höhe: 0.2 m; Programmversion: 3.1; Text3: 0; Plugin_Bezeichnung: MainObject; Plugin_Objektname: SmartPartCompressed; Version: 1.1; Abstand_Öffn_Unten: 9.85 m; ash T_Feuchtebeständigkeit: nein; Feuerwiderstandsklasse~: nein
WV 1.1 | H2 Ebene +2 |  | 1213Sma0813718668 |  | VUK1 - Wäschehalter | St | Trockenbauarbeiten | SmartPart | WV 1.1 |  |  |  | 3.75 |  |  |  |  | - | AllplanAttributes - Text1: WA2009; UK: 0 m; OK: 0 m; V6: 0 m; V7: 0 m; V8: 0 m; V9: 0; Länge: 1 m; Dicke: 0.025 m; Höhe: 0.2 m; Programmversion: 3.1; Text3: 0; Plugin_Bezeichnung: MainObject; Plugin_Objektname: SmartPartCompressed; Version: 1.1; Abstand_Öffn_Unten: 9.125 m; ash T_Feuchtebeständigkeit: nein; Feuerwiderstandsklasse~: nein
WV 1.1 | H2 Ebene +2 |  | 1213Sma0813718352 |  | VUK1 - Desinfektionsmittelspender | St | Trockenbauarbeiten | SmartPart | WV 1.1 |  |  |  | 3.75 |  |  |  |  | - | AllplanAttributes - Text1: WA2018; UK: 0 m; OK: 0 m; V6: 0 m; V7: 0 m; V8: 0 m; V9: 0; Länge: 2.08 m; Dicke: 0.025 m; Höhe: 0.25 m; Programmversion: 3.1; Text3: 0; Plugin_Bezeichnung: MainObject; Plugin_Objektname: SmartPartCompressed; Version: 1.1; Abstand_Öffn_Unten: 7.5 m; ash T_Feuchtebeständigkeit: nein; Feuerwiderstandsklasse~: nein
WV 1.1 | H2 Ebene +2 |  | 1213Sma0813718366 |  | VUK1 - Desinfektionsmittelspender | St | Trockenbauarbeiten | SmartPart | WV 1.1 |  |  |  | 3.75 |  |  |  |  | - | AllplanAttributes - Text1: WA2018; UK: 0 m; OK: 0 m; V6: 0 m; V7: 0 m; V8: 0 m; V9: 0; Länge: 0.64 m; Dicke: 0.025 m; Höhe: 0.25 m; Programmversion: 3.1; Text3: 0; Plugin_Bezeichnung: MainObject; Plugin_Objektname: SmartPartCompressed; Version: 1.1; Abstand_Öffn_Unten: 7.5 m; ash T_Feuchtebeständigkeit: nein; Feuerwiderstandsklasse~: nein
WV 1.1 | H2 Ebene +2 |  | 1213Sma0813718396 |  | VUK1 - Desinfektionsmittelspender | St | Trockenbauarbeiten | SmartPart | WV 1.1 |  |  |  | 3.75 |  |  |  |  | - | AllplanAttributes - Text1: WA2018; UK: 0 m; OK: 0 m; V6: 0 m; V7: 0 m; V8: 0 m; V9: 0; Länge: 2.98 m; Dicke: 0.025 m; Höhe: 0.25 m; Programmversion: 3.1; Text3: 0; Plugin_Bezeichnung: MainObject; Plugin_Objektname: SmartPartCompressed; Version: 1.1; Abstand_Öffn_Unten: 7.5 m; ash T_Feuchtebeständigkeit: nein; Feuerwiderstandsklasse~: nein
WV 1.1 | H2 Ebene +2 |  | 1213Sma0813718380 |  | VUK1 - Desinfektionsmittelspender | St | Trockenbauarbeiten | SmartPart | WV 1.1 |  |  |  | 3.75 |  |  |  |  | - | AllplanAttributes - Text1: WA2018; UK: 0 m; OK: 0 m; V6: 0 m; V7: 0 m; V8: 0 m; V9: 0; Länge: 0.27 m; Dicke: 0.025 m; Höhe: 0.25 m; Programmversion: 3.1; Text3: 0; Plugin_Bezeichnung: MainObject; Plugin_Objektname: SmartPartCompressed; Version: 1.1; Abstand_Öffn_Unten: 7.5 m; ash T_Feuchtebeständigkeit: nein; Feuerwiderstandsklasse~: nein
WV 1.1 | H2 Ebene +2 |  | 1213Sma0813717295 |  | VUK1 - Desinfektionsmittelspender | St | Trockenbauarbeiten | SmartPart | WV 1.1 |  |  |  | 3.75 |  |  |  |  | - | AllplanAttributes - Text1: WA2020; UK: 0 m; OK: 0 m; V6: 0 m; V7: 0 m; V8: 0 m; V9: 0; Länge: 0.3 m; Dicke: 0.025 m; Höhe: 0.7 m; Programmversion: 3.1; Text3: 0; Plugin_Bezeichnung: MainObject; Plugin_Objektname: SmartPartCompressed; Version: 1.1; Abstand_Öffn_Unten: 8.35 m; ash T_Feuchtebeständigkeit: nein; Feuerwiderstandsklasse~: nein
WV 1.1 | H2 Ebene +2 |  | 1213Sma0813717774 |  | VUK1 - Monitor | St | Trockenbauarbeiten | SmartPart | WV 1.1 |  |  |  | 3.75 |  |  |  |  | - | AllplanAttributes - Text1: WA2030; UK: 0 m; OK: 0 m; V6: 0 m; V7: 0 m; V8: 0 m; V9: 0; Länge: 1.2 m; Dicke: 0.025 m; Höhe: 1 m; Programmversion: 3.1; Text3: 0; Plugin_Bezeichnung: MainObject; Plugin_Objektname: SmartPartCompressed; Version: 1.1; Abstand_Öffn_Unten: 8.6 m; ash T_Feuchtebeständigkeit: nein; Feuerwiderstandsklasse~: nein
WV 1.1 | H2 Ebene +2 |  | 1213Sma0813717519 |  | VUK1 - Hängeschrank | St | Trockenbauarbeiten | SmartPart | WV 1.1 |  |  |  | 3.75 |  |  |  |  | - | AllplanAttributes - Text1: WA2012; UK: 0 m; OK: 0 m; V6: 0 m; V7: 0 m; V8: 0 m; V9: 0; Länge: 2.46 m; Dicke: 0.025 m; Höhe: 0.2 m; Programmversion: 3.1; Text3: 0; Plugin_Bezeichnung: MainObject; Plugin_Objektname: SmartPartCompressed; Version: 1.1; Abstand_Öffn_Unten: 9.85 m; ash T_Feuchtebeständigkeit: nein; Feuerwiderstandsklasse~: nein
WV 1.1 | H2 Ebene +2 |  | 1213Sma0813717505 |  | VUK5 - Handlauf | St | Trockenbauarbeiten | SmartPart | WV 1.1 |  |  |  | 3.75 |  |  |  |  | - | AllplanAttributes - Text1: WA; UK: 0 m; OK: 0 m; V6: 0 m; V7: 0 m; V8: 0 m; V9: 0; Länge: 0.7 m; Dicke: 0.025 m; Höhe: 0.2 m; Programmversion: 3.1; Text3: 0; Plugin_Bezeichnung: MainObject; Plugin_Objektname: SmartPartCompressed; Version: 1.1; Abstand_Öffn_Unten: 8.4 m; ash T_Feuchtebeständigkeit: nein; Feuerwiderstandsklasse~: nein
WV 1.1 | H2 Ebene +2 |  | 1213Sma0813717491 |  | VUK5 - Handlauf | St | Trockenbauarbeiten | SmartPart | WV 1.1 |  |  |  | 3.75 |  |  |  |  | - | AllplanAttributes - Text1: WA; UK: 0 m; OK: 0 m; V6: 0 m; V7: 0 m; V8: 0 m; V9: 0; Länge: 5.4 m; Dicke: 0.025 m; Höhe: 0.2 m; Programmversion: 3.1; Text3: 0; Plugin_Bezeichnung: MainObject; Plugin_Objektname: SmartPartCompressed; Version: 1.1; Abstand_Öffn_Unten: 8.4 m; ash T_Feuchtebeständigkeit: nein; Feuerwiderstandsklasse~: nein
WV 1.1 | H2 Ebene +2 |  | 1213Sma0813718189 |  | VUK2 | St | Trockenbauarbeiten | SmartPart | WV 1.1 |  |  |  | 3.75 |  |  |  |  | - | AllplanAttributes - UK: 0 m; OK: 0 m; V6: 0 m; V7: 0 m; V8: 0 m; V9: 0; Länge: 0.59 m; Dicke: 0.018 m; Höhe: 0.3 m; Programmversion: 3.1; Text3: 0; Plugin_Bezeichnung: MainObject; Plugin_Objektname: SmartPartCompressed; Version: 1.1; Abstand_Öffn_Unten: 9.9 m; ash T_Feuchtebeständigkeit: nein; Feuerwiderstandsklasse~: nein
WV 1.1 | H2 Ebene +2 |  | 1213Sma0813718246 |  | VUK2 | St | Trockenbauarbeiten | SmartPart | WV 1.1 |  |  |  | 3.75 |  |  |  |  | - | AllplanAttributes - UK: 0 m; OK: 0 m; V6: 0 m; V7: 0 m; V8: 0 m; V9: 0; Länge: 0.59 m; Dicke: 0.018 m; Höhe: 0.3 m; Programmversion: 3.1; Text3: 0; Plugin_Bezeichnung: MainObject; Plugin_Objektname: SmartPartCompressed; Version: 1.1; Abstand_Öffn_Unten: 9.9 m; ash T_Feuchtebeständigkeit: nein; Feuerwiderstandsklasse~: nein
WV 1.1 | H2 Ebene +2 |  | 1213Sma0813718192 |  | VUK2 | St | Trockenbauarbeiten | SmartPart | WV 1.1 |  |  |  | 3.75 |  |  |  |  | - | AllplanAttributes - UK: 0 m; OK: 0 m; V6: 0 m; V7: 0 m; V8: 0 m; V9: 0; Länge: 0.59 m; Dicke: 0.018 m; Höhe: 0.3 m; Programmversion: 3.1; Text3: 0; Plugin_Bezeichnung: MainObject; Plugin_Objektname: SmartPartCompressed; Version: 1.1; Abstand_Öffn_Unten: 9.1 m; ash T_Feuchtebeständigkeit: nein; Feuerwiderstandsklasse~: nein
WV 1.1 | H2 Ebene +2 |  | 1213Sma0813718249 |  | VUK2 | St | Trockenbauarbeiten | SmartPart | WV 1.1 |  |  |  | 3.75 |  |  |  |  | - | AllplanAttributes - UK: 0 m; OK: 0 m; V6: 0 m; V7: 0 m; V8: 0 m; V9: 0; Länge: 0.59 m; Dicke: 0.018 m; Höhe: 0.3 m; Programmversion: 3.1; Text3: 0; Plugin_Bezeichnung: MainObject; Plugin_Objektname: SmartPartCompressed; Version: 1.1; Abstand_Öffn_Unten: 9.1 m; ash T_Feuchtebeständigkeit: nein; Feuerwiderstandsklasse~: nein
WV 1.1 | H2 Ebene +2 |  | 1213Sma0813718217 |  | VUK2 | St | Trockenbauarbeiten | SmartPart | WV 1.1 |  |  |  | 3.75 |  |  |  |  | - | AllplanAttributes - UK: 0 m; OK: 0 m; V6: 0 m; V7: 0 m; V8: 0 m; V9: 0; Länge: 0.5 m; Dicke: 0.018 m; Höhe: 0.3 m; Programmversion: 3.1; Text3: 0; Plugin_Bezeichnung: MainObject; Plugin_Objektname: SmartPartCompressed; Version: 1.1; Abstand_Öffn_Unten: 9.9 m; ash T_Feuchtebeständigkeit: nein; Feuerwiderstandsklasse~: nein
WV 1.1 | H2 Ebene +2 |  | 1213Sma0813718274 |  | VUK2 | St | Trockenbauarbeiten | SmartPart | WV 1.1 |  |  |  | 3.75 |  |  |  |  | - | AllplanAttributes - UK: 0 m; OK: 0 m; V6: 0 m; V7: 0 m; V8: 0 m; V9: 0; Länge: 0.5 m; Dicke: 0.018 m; Höhe: 0.3 m; Programmversion: 3.1; Text3: 0; Plugin_Bezeichnung: MainObject; Plugin_Objektname: SmartPartCompressed; Version: 1.1; Abstand_Öffn_Unten: 9.9 m; ash T_Feuchtebeständigkeit: nein; Feuerwiderstandsklasse~: nein
WV 1.1 | H2 Ebene +2 |  | 1213Sma0813718231 |  | VUK2 | St | Trockenbauarbeiten | SmartPart | WV 1.1 |  |  |  | 3.75 |  |  |  |  | - | AllplanAttributes - UK: 0 m; OK: 0 m; V6: 0 m; V7: 0 m; V8: 0 m; V9: 0; Länge: 0.5 m; Dicke: 0.018 m; Höhe: 0.3 m; Programmversion: 3.1; Text3: 0; Plugin_Bezeichnung: MainObject; Plugin_Objektname: SmartPartCompressed; Version: 1.1; Abstand_Öffn_Unten: 9.1 m; ash T_Feuchtebeständigkeit: nein; Feuerwiderstandsklasse~: nein
WV 1.1 | H2 Ebene +2 |  | 1213Sma0813718288 |  | VUK2 | St | Trockenbauarbeiten | SmartPart | WV 1.1 |  |  |  | 3.75 |  |  |  |  | - | AllplanAttributes - UK: 0 m; OK: 0 m; V6: 0 m; V7: 0 m; V8: 0 m; V9: 0; Länge: 0.5 m; Dicke: 0.018 m; Höhe: 0.3 m; Programmversion: 3.1; Text3: 0; Plugin_Bezeichnung: MainObject; Plugin_Objektname: SmartPartCompressed; Version: 1.1; Abstand_Öffn_Unten: 9.1 m; ash T_Feuchtebeständigkeit: nein; Feuerwiderstandsklasse~: nein
WV 1.1 | H2 Ebene +2 |  | 1213Sma0813717533 |  | VUK1 - Hängeschrank | St | Trockenbauarbeiten | SmartPart | WV 1.1 |  |  |  | 3.75 |  |  |  |  | - | AllplanAttributes - Text1: WA2020; UK: 0 m; OK: 0 m; V6: 0 m; V7: 0 m; V8: 0 m; V9: 0; Länge: 0.8 m; Dicke: 0.025 m; Höhe: 0.2 m; Programmversion: 3.1; Text3: 0; Plugin_Bezeichnung: MainObject; Plugin_Objektname: SmartPartCompressed; Version: 1.1; Abstand_Öffn_Unten: 9.7 m; ash T_Feuchtebeständigkeit: nein; Feuerwiderstandsklasse~: nein
WV 1.1 | H2 Ebene +2 |  | 1213Sma0813718639 |  | VUK5 - Handlauf | St | Trockenbauarbeiten | SmartPart | WV 1.1 |  |  |  | 3.75 |  |  |  |  | - | AllplanAttributes - Text1: WA; UK: 0 m; OK: 0 m; V6: 0 m; V7: 0 m; V8: 0 m; V9: 0; Länge: 1.65 m; Dicke: 0.025 m; Höhe: 0.2 m; Programmversion: 3.1; Text3: 0; Plugin_Bezeichnung: MainObject; Plugin_Objektname: SmartPartCompressed; Version: 1.1; Abstand_Öffn_Unten: 8.4 m; ash T_Feuchtebeständigkeit: nein; Feuerwiderstandsklasse~: nein
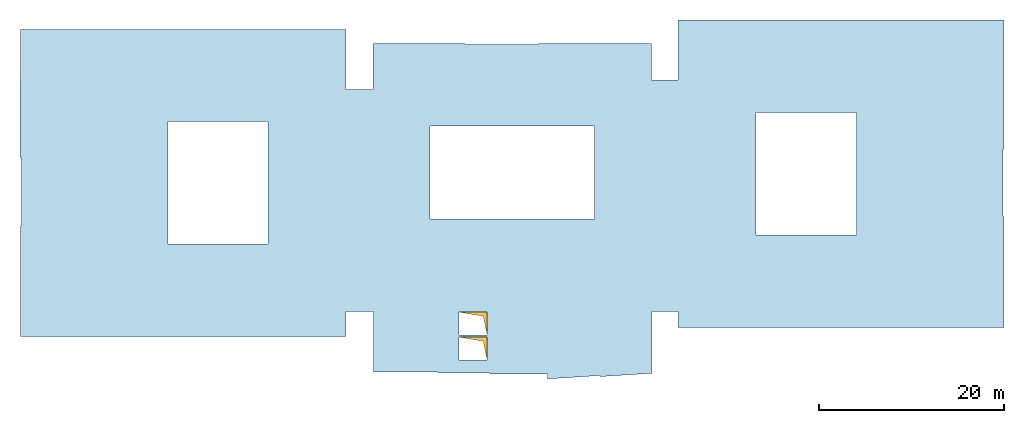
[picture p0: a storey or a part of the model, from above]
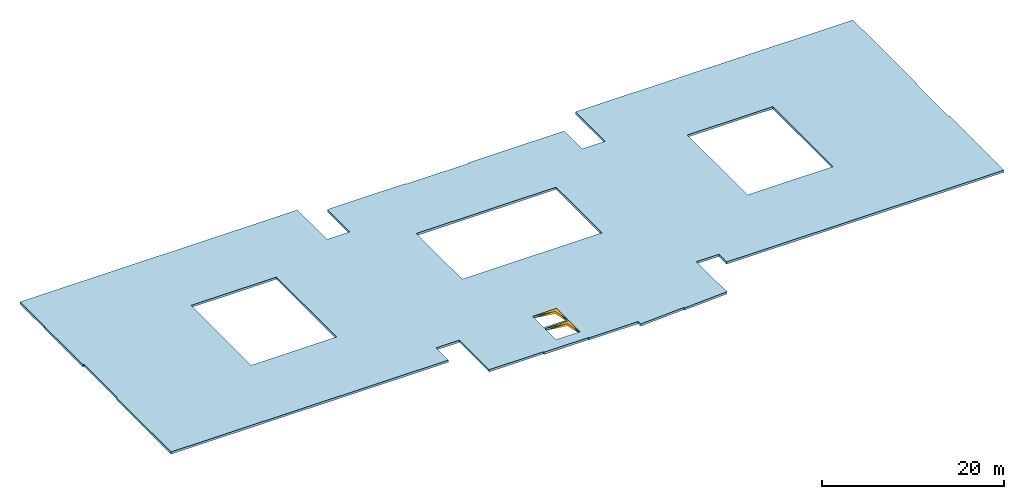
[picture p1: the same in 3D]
Properties of the parts of a building model (IFC4), part 54 of 80

# IfcWall (6826)
Name | In | Material | Allright_Bauteil_ID | 2D Interaktion | Codetext | Abrechnungsart | Gewerk | Objektname | Bezeichnung | AllplanAttributes, Material | Typ = SurfaceSpreadOfFlame | Brandschutzklasse | OKFF | P_ID | Status | LoadBearing | IsExternal | FireRating | ThermalTransmittance (W/K/m2) | Combustible | AcousticRating | Compartmentation | Reference
WV 1.1 | H2 Ebene +2 |  | 1213Sma0813717056 |  | VUK1 - Lichtleiste (ELT) | St | Trockenbauarbeiten | SmartPart | WV 1.1 |  |  |  | 3.75 |  |  |  |  | - | AllplanAttributes - Text1: WA2001; UK: 0 m; OK: 0 m; V6: 0 m; V7: 0 m; V8: 0 m; V9: 0; Länge: 1.2 m; Dicke: 0.025 m; Höhe: 0.15 m; Programmversion: 3.1; Text3: 0; Plugin_Bezeichnung: MainObject; Plugin_Objektname: SmartPartCompressed; Version: 1.1; Abstand_Öffn_Unten: 9.125 m; ash T_Feuchtebeständigkeit: nein; Feuerwiderstandsklasse~: nein
 | H2 Ebene +2 | WI-LB | 1213Wa 0812986179 |  | Codetext | m² | Trockenbauarbeiten | Wand | Innenwand 1-Schalig | WI-LB | 0 | A | 7.5 | 1213HWa0812968046 | NEW | no | no | REI 30-A1 - D,s2-d0 +A1 | 0 | no | 0 | no | Codetext | AllplanAttributes - Ortscode_Geschoßbezeichnung: E02; W_Deckenanschluss: Gleitender Deckenanschluss Fall 01; ash_W_Trockenbau_Qualitäten: 1b
 | H2 Ebene +2 | WI-LB | 1213Wa 0812986264 |  | Codetext | m² | Trockenbauarbeiten | Wand | Innenwand 1-Schalig | WI-LB | 0 | A | 7.5 | 1213HWa0812968047 | NEW | no | no | REI 30-A1 - D,s2-d0 +A1 | 0 | no | 0 | no | Codetext | AllplanAttributes - Ortscode_Geschoßbezeichnung: E02; W_Deckenanschluss: Gleitender Deckenanschluss Fall 01; ash_W_Trockenbau_Qualitäten: 1b
 | H2 Ebene +2 | WI-LB | 1213Wa 0812970458 | yes | Codetext | m² | Trockenbauarbeiten | Wand | Außenwand 1-Schalig | WI-LB | 0 | A | 7.5 | 1213HWa0812968048 | NEW | no | no | REI 60-A1 - D,s2-d0 /A1 | 0 | no | 0 | no | Codetext | AllplanAttributes - Ortscode_Geschoßbezeichnung: E02; W_Deckenanschluss: Gleitender Deckenanschluss Fall 01; ash_W_Trockenbau_Qualitäten: 1b
 | H2 Ebene +2 | WI-LB | 1213Wa 0812970446 | yes | Codetext | m² | Trockenbauarbeiten | Wand | Innenwand 1-Schalig | WI-LB | 0 | A | 7.5 | 1213HWa0812968056 | NEW |  | no | REI 60-A1 - D,s2-d0 /A1 | 0 | no | 0 | no | Codetext | AllplanAttributes - Ortscode_Geschoßbezeichnung: E02; W_Deckenanschluss: Gleitender Deckenanschluss Fall 01; ash_W_Trockenbau_Qualitäten: 1b
 | H2 Ebene +2 | WI-LB | 1213Wa 0812970444 | yes | Codetext | m² | Trockenbauarbeiten | Wand | Innenwand 1-Schalig | WI-LB | 0 | A | 7.5 | 1213HWa0812968057 | NEW | no | no | REI 60-A1 - D,s2-d0 /A1 | 0 | no | 0 | no | Codetext | AllplanAttributes - Ortscode_Geschoßbezeichnung: E02; W_Deckenanschluss: Gleitender Deckenanschluss Fall 01; ash_W_Trockenbau_Qualitäten: 1b
 | H2 Ebene +2 | WI-LB | 1213Wa 0812970960 | yes | Codetext | m² | Trockenbauarbeiten | Wand | Außenwand 1-Schalig | WI-LB | 0 | A | 7.5 | 1213HWa0812968058 | NEW | no | no | REI 60-A1 - D,s2-d0 /A1 | 0 | no | 0 | no | Codetext | AllplanAttributes - Ortscode_Geschoßbezeichnung: E02; W_Deckenanschluss: Gleitender Deckenanschluss Fall 01; ash_W_Trockenbau_Qualitäten: 1b
 | H2 Ebene +2 | WI-LB | 1213Wa 0812971169 | yes | Codetext | m² | Trockenbauarbeiten | Wand | Innenwand 1-Schalig | WI-LB | 0 | A | 7.5 | 1213HWa0812968061 | NEW |  | no | 0 | 0 | no | 0 | no | Codetext | AllplanAttributes - Ortscode_Geschoßbezeichnung: E02; W_Deckenanschluss: Gleitender Deckenanschluss Fall 01; ash_W_Trockenbau_Qualitäten: 1b
 | H2 Ebene +2 | WI-STB | 1213Wa 0812971166 | yes | Codetext | m² | Zimmer- und Holzbauarbeiten | Wand | Innenwand 1-Schalig | WI-STB | 0 | A | 7.5 | 1213HWa0812968063 | NEW | yes | no | REI 60-A1 - D,s2-d0 /A1 | 0 | no | 0 | no | Codetext | AllplanAttributes - Ortscode_Geschoßbezeichnung: E02
 | H2 Ebene +2 | WI-STB | 1213Wa 0812971163 | yes | Codetext | m² | Zimmer- und Holzbauarbeiten | Wand | Innenwand 1-Schalig | WI-STB | 0 | A | 7.5 | 1213HWa0812968064 | NEW | yes | no | REI 60-A1 - D,s2-d0 /A1 | 0 | no | 0 | no | Codetext | AllplanAttributes - Ortscode_Geschoßbezeichnung: E02
 | H2 Ebene +2 | WI-STB | 1213Wa 0812970371 | yes | Codetext | m² | Zimmer- und Holzbauarbeiten | Wand | Außenwand 1-Schalig | WI-STB | 0 | A | 7.5 | 1213HWa0812968065 | NEW | yes | no | REI 60-A1 - D,s2-d0 /A1 | 0 | no | 0 | no | Codetext | AllplanAttributes - Ortscode_Geschoßbezeichnung: E02
 | H2 Ebene +2 | WI-STB | 1213Wa 0812970337 | yes | Codetext | m² | Zimmer- und Holzbauarbeiten | Wand | Außenwand 1-Schalig | WI-STB | 0 | A | 7.5 | 1213HWa0812968069 | NEW | yes | no | REI 60-A1 - D,s2-d0 /A1 | 0 | no | 0 | no | Codetext | AllplanAttributes - Ortscode_Geschoßbezeichnung: E02
 | H2 Ebene +2 | WI-STB | 1213Wa 0812970325 | yes | Codetext | m² | Zimmer- und Holzbauarbeiten | Wand | Außenwand 1-Schalig | WI-STB | 0 | A | 7.5 | 1213HWa0812968071 | NEW | yes | no | REI 60-A1 - D,s2-d0 /A1 | 0 | no | 0 | no | Codetext | AllplanAttributes - Ortscode_Geschoßbezeichnung: E02
 | H2 Ebene +2 | WI-STB | 1213Wa 0812970379 | yes | Codetext | m² | Zimmer- und Holzbauarbeiten | Wand | Außenwand 1-Schalig | WI-STB | 0 | A | 7.5 | 1213HWa0812968072 | NEW | yes | no | REI 60-A1 - D,s2-d0 /A1 | 0 | no | 0 | no | Codetext | AllplanAttributes - Ortscode_Geschoßbezeichnung: E02
 | H2 Ebene +2 | WI-LB | 1213Wa 0812986176 | yes | Codetext | m² | Trockenbauarbeiten | Wand | Innenwand 1-Schalig | WI-LB | 0 | A | 7.5 | 1213HWa0812968079 | NEW | no | no | 0 | 0 | no | 0 | no | Codetext | AllplanAttributes - Ortscode_Geschoßbezeichnung: E02; W_Deckenanschluss: Gleitender Deckenanschluss Fall 01; ash_W_Trockenbau_Qualitäten: 1b
 | H2 Ebene +2 | WI-LB | 1213Wa 0812985996 | yes | Codetext | m² | Trockenbauarbeiten | Wand | Außenwand 1-Schalig | WI-LB | 0 | A | 7.5 | 1213HWa0812968080 | NEW | no | no | REI 60-A1 - D,s2-d0 /A1 | 0 | no | 0 | no | Codetext | AllplanAttributes - Ortscode_Geschoßbezeichnung: E02; W_Deckenanschluss: Gleitender Deckenanschluss Fall 01; ash_W_Trockenbau_Qualitäten: 1b
 | H2 Ebene +2 | WA-STB | 1213Wa 0812971287 | yes | Codetext | m² | Zimmer- und Holzbauarbeiten | Wand | Außenwand 1-Schalig | WA-STB | 0 | A | 7.5 | 1213HWa0812968091 | NEW | yes | no | REI 60-A1 - D,s2-d0 /A1 | 0 | no | 0 | no | Codetext | AllplanAttributes - Ortscode_Geschoßbezeichnung: E02
 | H2 Ebene +2 | WI-LB | 1213Wa 0812970450 | yes | Codetext | m² | Trockenbauarbeiten | Wand | Innenwand 1-Schalig | WI-LB | 0 | A | 7.5 | 1213HWa0812968096 | NEW | no | no | REI 60-A1 - D,s2-d0 /A1 | 0 | no | 0 | no | Codetext | AllplanAttributes - Ortscode_Geschoßbezeichnung: E02; W_Deckenanschluss: Gleitender Deckenanschluss Fall 01; ash_W_Trockenbau_Qualitäten: 1b
 | H2 Ebene +2 | WI-LB | 1213Wa 0812970400 | yes | Codetext | m² | Trockenbauarbeiten | Wand | Innenwand 1-Schalig | WI-LB | 0 | A | 7.5 | 1213HWa0812968101 | NEW |  | no | REI 60-A1 - D,s2-d0 /A1 | 0 | no | 0 | no | Codetext | AllplanAttributes - Ortscode_Geschoßbezeichnung: E02; W_Deckenanschluss: Gleitender Deckenanschluss Fall 01; ash_W_Trockenbau_Qualitäten: 13
 | H2 Ebene +2 | WI-LB | 1213Wa 0812970275 |  | Codetext | m² | Trockenbauarbeiten | Wand | Innenwand 1-Schalig | WI-LB | 0 | A | 7.5 | 1213HWa0812968109 | NEW |  | no | REI 60-A1 - D,s2-d0 +A1 | 0 | no |  | no | Codetext | AllplanAttributes - Ortscode_Geschoßbezeichnung: E02; W_Deckenanschluss: Gleitender Deckenanschluss Fall 01; ash_W_Trockenbau_Qualitäten: 1b
 | H2 Ebene +2 | WI-LB | 1213Wa 0812970958 | yes | Codetext | m² | Trockenbauarbeiten | Wand | Innenwand 1-Schalig | WI-LB | 0 | A | 7.5 | 1213HWa0812968111 | NEW | no | no | REI 60-A1 - D,s2-d0 /A1 | 0 | no | 0 | no | Codetext | AllplanAttributes - Ortscode_Geschoßbezeichnung: E02; W_Deckenanschluss: Gleitender Deckenanschluss Fall 01; ash_W_Trockenbau_Qualitäten: 1b
 | H2 Ebene +2 | WI-HW 60 | 1213Wa 0812970522 | yes | Codetext | m² | Zimmer- und Holzbauarbeiten | Wand | Innenwand 1-Schalig | WI-HW 60 | 0 | A | 7.5 | 1213HWa0812968125 | NEW |  | no | REI 60-A1 - D,s2-d0 +A1 | 0 | no | 0 | no | Codetext | AllplanAttributes - Ortscode_Geschoßbezeichnung: E02; ash W_laufende Nr. Statik: 3 (W 3.0)
 | H2 Ebene +2 | WI-HW 60 | 1213Wa 0812970524 | yes | Codetext | m² | Zimmer- und Holzbauarbeiten | Wand | Innenwand 1-Schalig | WI-HW 60 | 0 | A | 7.5 | 1213HWa0812968126 | NEW |  | no | REI 60-A1 - D,s2-d0 +A1 | 0 | no | 0 | no | Codetext | AllplanAttributes - Ortscode_Geschoßbezeichnung: E02; ash W_laufende Nr. Statik: 3 (W 3.0)
 | H2 Ebene +2 | WI-HW 60 | 1213Wa 0812986430 | yes | Codetext | m² | Zimmer- und Holzbauarbeiten | Wand | Innenwand 1-Schalig | WI-HW 60 | 0 | A | 7.5 | 1213HWa0812968127 | NEW | yes | no | REI 30-A1 - D,s2-d0 +A1 | 0 | no | 0 | no | Codetext | AllplanAttributes - Ortscode_Geschoßbezeichnung: E02; ash W_laufende Nr. Statik: 3 (W 3.0)
 | H2 Ebene +2 | WI-HW 60 | 1213Wa 0812970420 | yes | Codetext | m² | Zimmer- und Holzbauarbeiten | Wand | Innenwand 1-Schalig | WI-HW 60 | 0 | A | 7.5 | 1213HWa0812968128 | NEW | yes | no | REI 30-A1 - D,s2-d0 +A1 | 0 | no | 0 | no | Codetext | AllplanAttributes - Ortscode_Geschoßbezeichnung: E02; ash W_laufende Nr. Statik: 3 (W 3.0)
 | H2 Ebene +2 | WI-HW 60 | 1213Wa 0812971266 | yes | Codetext | m² | Zimmer- und Holzbauarbeiten | Wand | Innenwand 1-Schalig | WI-HW 60 | 0 | A | 7.5 | 1213HWa0812968143 | NEW | yes | no | REI 60-A1 - D,s2-d0 /A1 | 0 | no | 0 | no | Codetext | AllplanAttributes - Ortscode_Geschoßbezeichnung: E02; ash W_laufende Nr. Statik: 3 (W 3.0)
 | H2 Ebene +2 | WI-HW 60 | 1213Wa 0812970513 | yes | Codetext | m² | Zimmer- und Holzbauarbeiten | Wand | Innenwand 1-Schalig | WI-HW 60 | 0 | A | 7.5 | 1213HWa0812968152 | NEW | yes | no | REI 60-A1 - D,s2-d0 +A1 | 0 | no | 52 | no | Codetext | AllplanAttributes - Ortscode_Geschoßbezeichnung: E02; ash W_laufende Nr. Statik: 3 (W 3.0)
 | H2 Ebene +2 | WI-HW 60 | 1213Wa 0812986268 | yes | Codetext | m² | Zimmer- und Holzbauarbeiten | Wand | Innenwand 1-Schalig | WI-HW 60 | 0 | A | 7.5 | 1213HWa0812968186 | NEW | yes | no | 0 | 0 | no | 0 | no | Codetext | AllplanAttributes - Ortscode_Geschoßbezeichnung: E02; ash W_laufende Nr. Statik: 3 (W 3.0)
 | H2 Ebene +2 | WI-HW 60 | 1213Wa 0812986261 | yes | Codetext | m² | Zimmer- und Holzbauarbeiten | Wand | Innenwand 1-Schalig | WI-HW 60 | 0 | A | 7.5 | 1213HWa0812968189 | NEW | yes | no | REI 30-A1 - D,s2-d0 +A1 | 0 | no | 0 | no | Codetext | AllplanAttributes - Ortscode_Geschoßbezeichnung: E02; ash W_laufende Nr. Statik: 3 (W 3.0)
 | H2 Ebene +2 | WI-HW 60 | 1213Wa 0812970417 | yes | Codetext | m² | Zimmer- und Holzbauarbeiten | Wand | Innenwand 1-Schalig | WI-HW 60 | 0 | A | 7.5 | 1213HWa0812968191 | NEW | yes | no | REI 30-A1 - D,s2-d0 +A1 | 0 | no | 0 | no | Codetext | AllplanAttributes - Ortscode_Geschoßbezeichnung: E02; ash W_laufende Nr. Statik: 3 (W 3.0)
 | H2 Ebene +2 | WI-HW 60 | 1213Wa 0812970464 | yes | Codetext | m² | Zimmer- und Holzbauarbeiten | Wand | Innenwand 1-Schalig | WI-HW 60 | 0 | A | 7.5 | 1213HWa0812968193 | NEW | yes | no | REI 60-A1 - D,s2-d0 +A1 | 0 | no | 0 | no | Codetext | AllplanAttributes - Ortscode_Geschoßbezeichnung: E02; ash W_laufende Nr. Statik: 3 (W 3.0)
 | H2 Ebene +2 | WI-HW 60 | 1213Wa 0812971271 | yes | Codetext | m² | Zimmer- und Holzbauarbeiten | Wand | Innenwand 1-Schalig | WI-HW 60 | 0 | A | 7.5 | 1213HWa0812968195 | NEW | yes | no | REI 60-A1 - D,s2-d0 +A1 | 0 | no | 0 | no | Codetext | AllplanAttributes - Ortscode_Geschoßbezeichnung: E02; ash W_laufende Nr. Statik: 3 (W 3.0)
 | H2 Ebene +2 | WI-LB | 1213Wa 0812970860 |  | Codetext | m² | Trockenbauarbeiten | Wand |  |  | 0 | A | 7.5 | 1213HWa0812968210 | NEW | no | no | 0 | 0 | no | 0 | no | Codetext | AllplanAttributes - Ortscode_Geschoßbezeichnung: E02; W_Deckenanschluss: Gleitender Deckenanschluss Fall 03; ash_W_Trockenbau_Qualitäten: 10a
 | H2 Ebene +2 | WI-LB | 1213Wa 0812986333 |  | Codetext | m² | Trockenbauarbeiten | Wand |  |  | 0 | A | 7.5 | 1213HWa0812968211 | NEW | no | no | 0 | 0 | no | 0 | no | Codetext | AllplanAttributes - Ortscode_Geschoßbezeichnung: E02; W_Deckenanschluss: Gleitender Deckenanschluss Fall 03; ash_W_Trockenbau_Qualitäten: 10a
 | H2 Ebene +2 | WI-LB | 1213Wa 0812986329 |  | Codetext | m² | Trockenbauarbeiten | Wand |  |  | 0 | A | 7.5 | 1213HWa0812968212 | NEW | no | no | 0 | 0 | no | 0 | no | Codetext | AllplanAttributes - Ortscode_Geschoßbezeichnung: E02; W_Deckenanschluss: Gleitender Deckenanschluss Fall 03; ash_W_Trockenbau_Qualitäten: 10a
 | H2 Ebene +2 | WI-LB | 1213Wa 0812986325 |  | Codetext | m² | Trockenbauarbeiten | Wand |  |  | 0 | A | 7.5 | 1213HWa0812968213 | NEW | no | no | 0 | 0 | no | 0 | no | Codetext | AllplanAttributes - Ortscode_Geschoßbezeichnung: E02; W_Deckenanschluss: Gleitender Deckenanschluss Fall 03; ash_W_Trockenbau_Qualitäten: 10a
 | H2 Ebene +2 | WI-LB | 1213Wa 0812970864 |  | Codetext | m² | Trockenbauarbeiten | Wand |  |  | 0 | A | 7.5 | 1213HWa0812968214 | NEW | no | no | 0 | 0 | no | 0 | no | Codetext | AllplanAttributes - Ortscode_Geschoßbezeichnung: E02; W_Deckenanschluss: Gleitender Deckenanschluss Fall 03; ash_W_Trockenbau_Qualitäten: 10a
 | H2 Ebene +2 | WI-LB | 1213Wa 0812986321 |  | Codetext | m² | Trockenbauarbeiten | Wand |  |  | 0 | A | 7.5 | 1213HWa0812968215 | NEW | no | no | 0 | 0 | no | 0 | no | Codetext | AllplanAttributes - Ortscode_Geschoßbezeichnung: E02; W_Deckenanschluss: Gleitender Deckenanschluss Fall 03; ash_W_Trockenbau_Qualitäten: 10a
 | H2 Ebene +2 | WI-LB | 1213Wa 0812970309 |  | Codetext | m² | Trockenbauarbeiten | Wand |  |  | 0 | A | 7.5 | 1213HWa0812968216 | NEW | no | no | 0 | 0 | no | 0 | no | Codetext | AllplanAttributes - Ortscode_Geschoßbezeichnung: E02; W_Deckenanschluss: Gleitender Deckenanschluss Fall 03; ash_W_Trockenbau_Qualitäten: 10a
 | H2 Ebene +2 | WI-LB | 1213Wa 0812986337 |  | Codetext | m² | Trockenbauarbeiten | Wand |  |  | 0 | A | 7.5 | 1213HWa0812968217 | NEW | no | no | 0 | 0 | no | 0 | no | Codetext | AllplanAttributes - Ortscode_Geschoßbezeichnung: E02; W_Deckenanschluss: Gleitender Deckenanschluss Fall 03; ash_W_Trockenbau_Qualitäten: 10a
 | H2 Ebene +2 | WI-LB | 1213Wa 0812986341 |  | Codetext | m² | Trockenbauarbeiten | Wand |  |  | 0 | A | 7.5 | 1213HWa0812968218 | NEW | no | no | 0 | 0 | no | 0 | no | Codetext | AllplanAttributes - Ortscode_Geschoßbezeichnung: E02; W_Deckenanschluss: Gleitender Deckenanschluss Fall 03; ash_W_Trockenbau_Qualitäten: 10a
 | H2 Ebene +2 | WI-LB | 1213Wa 0812970652 |  | Codetext | m² | Trockenbauarbeiten | Wand |  |  | 0 | A | 7.5 | 1213HWa0812968236 | NEW | no | no | 0 | 0 | no | 0 | no | Codetext | AllplanAttributes - Ortscode_Geschoßbezeichnung: E02; W_Deckenanschluss: Gleitender Deckenanschluss Fall 03; ash_W_Trockenbau_Qualitäten: 10a
 | H2 Ebene +2 | WI-LB | 1213Wa 0812970768 |  | Codetext | m² | Trockenbauarbeiten | Wand |  |  | 0 | A | 7.5 | 1213HWa0812968314 | NEW | no | no | 0 | 0 | no | 0 | no | Codetext | AllplanAttributes - Ortscode_Geschoßbezeichnung: E02; W_Deckenanschluss: Gleitender Deckenanschluss Fall 03; ash_W_Trockenbau_Qualitäten: 10a
 | H2 Ebene +2 | WI-LB | 1213Wa 0812986272 |  | Codetext | m² | Trockenbauarbeiten | Wand |  |  | 0 | A | 7.5 | 1213HWa0812968315 | NEW | no | no | 0 | 0 | no | 0 | no | Codetext | AllplanAttributes - Ortscode_Geschoßbezeichnung: E02; W_Deckenanschluss: Gleitender Deckenanschluss Fall 03; ash_W_Trockenbau_Qualitäten: 10a
 | H2 Ebene +2 | WI-LB | 1213Wa 0812970285 |  | Codetext | m² | Trockenbauarbeiten | Wand | Innenwand 1-Schalig | WI-LB | 0 | A | 7.5 | 1213HWa0812968325 | NEW | no | no | REI 60-A1 - D,s2-d0 +A1 | 0 | no | 0 | no | Codetext | AllplanAttributes - Ortscode_Geschoßbezeichnung: E02; W_Deckenanschluss: Gleitender Deckenanschluss Fall 01; ash_W_Trockenbau_Qualitäten: 1b
 | H2 Ebene +2 | WI-LB | 1213Wa 0812970273 | yes | Codetext | m² | Trockenbauarbeiten | Wand | Innenwand 1-Schalig | WI-LB | 0 | A | 7.5 | 1213HWa0812968328 | NEW | no | no | REI 60-A1 - D,s2-d0 +A1 | 0 | no | 0 | no | Codetext | AllplanAttributes - Ortscode_Geschoßbezeichnung: E02; W_Deckenanschluss: Gleitender Deckenanschluss Fall 01; ash_W_Trockenbau_Qualitäten: 1b
 | H2 Ebene +2 | WI-LB | 1213Wa 0812970684 |  | Codetext | m² | Trockenbauarbeiten | Wand |  |  | 0 | A | 7.5 | 1213HWa0812968340 | NEW | no | no | 0 | 0 | no | 0 | no | Codetext | AllplanAttributes - Ortscode_Geschoßbezeichnung: E02; W_Deckenanschluss: Gleitender Deckenanschluss Fall 03; ash_W_Trockenbau_Qualitäten: 10a
 | H2 Ebene +2 | WI-LB | 1213Wa 0812986222 |  | Codetext | m² | Trockenbauarbeiten | Wand |  |  | 0 | A | 7.5 | 1213HWa0812968341 | NEW | no | no | 0 | 0 | no | 0 | no | Codetext | AllplanAttributes - Ortscode_Geschoßbezeichnung: E02; W_Deckenanschluss: Gleitender Deckenanschluss Fall 03; ash_W_Trockenbau_Qualitäten: 10a
 | H2 Ebene +2 | WI-LB | 1213Wa 0812986226 |  | Codetext | m² | Trockenbauarbeiten | Wand |  |  | 0 | A | 7.5 | 1213HWa0812968342 | NEW | no | no | 0 | 0 | no | 0 | no | Codetext | AllplanAttributes - Ortscode_Geschoßbezeichnung: E02; W_Deckenanschluss: Gleitender Deckenanschluss Fall 03; ash_W_Trockenbau_Qualitäten: 10a
 | H2 Ebene +2 | WI-LB | 1213Wa 0812986103 |  | Codetext | m² | Trockenbauarbeiten | Wand |  |  | 0 | A | 7.5 | 1213HWa0812968343 | NEW | no | no | 0 | 0 | no | 0 | no | Codetext | AllplanAttributes - Ortscode_Geschoßbezeichnung: E02; W_Deckenanschluss: Gleitender Deckenanschluss Fall 03; ash_W_Trockenbau_Qualitäten: 10a
 | H2 Ebene +2 | WI-LB | 1213Wa 0812970674 |  | Codetext | m² | Trockenbauarbeiten | Wand |  |  | 0 | A | 7.5 | 1213HWa0812968344 | NEW | no | no | 0 | 0 | no | 0 | no | Codetext | AllplanAttributes - Ortscode_Geschoßbezeichnung: E02; W_Deckenanschluss: Gleitender Deckenanschluss Fall 03; ash_W_Trockenbau_Qualitäten: 10a
 | H2 Ebene +2 | WI-LB | 1213Wa 0812986214 |  | Codetext | m² | Trockenbauarbeiten | Wand |  |  | 0 | A | 7.5 | 1213HWa0812968345 | NEW | no | no | 0 | 0 | no | 0 | no | Codetext | AllplanAttributes - Ortscode_Geschoßbezeichnung: E02; W_Deckenanschluss: Gleitender Deckenanschluss Fall 03; ash_W_Trockenbau_Qualitäten: 10a
 | H2 Ebene +2 | WI-LB | 1213Wa 0812986218 |  | Codetext | m² | Trockenbauarbeiten | Wand |  |  | 0 | A | 7.5 | 1213HWa0812968346 | NEW | no | no | 0 | 0 | no | 0 | no | Codetext | AllplanAttributes - Ortscode_Geschoßbezeichnung: E02; W_Deckenanschluss: Gleitender Deckenanschluss Fall 03; ash_W_Trockenbau_Qualitäten: 10a
 | H2 Ebene +2 | WI-LB | 1213Wa 0812970679 |  | Codetext | m² | Trockenbauarbeiten | Wand |  |  | 0 | A | 7.5 | 1213HWa0812968347 | NEW | no | no | 0 | 0 | no | 0 | no | Codetext | AllplanAttributes - Ortscode_Geschoßbezeichnung: E02; W_Deckenanschluss: Gleitender Deckenanschluss Fall 03; ash_W_Trockenbau_Qualitäten: 10a
 | H2 Ebene +2 | WI-LB | 1213Wa 0812986107 |  | Codetext | m² | Trockenbauarbeiten | Wand |  |  | 0 | A | 7.5 | 1213HWa0812968348 | NEW | no | no | 0 | 0 | no | 0 | no | Codetext | AllplanAttributes - Ortscode_Geschoßbezeichnung: E02; W_Deckenanschluss: Gleitender Deckenanschluss Fall 03; ash_W_Trockenbau_Qualitäten: 10a
 | H2 Ebene +2 | WI-LB | 1213Wa 0812986425 | yes | Codetext | m² | Trockenbauarbeiten | Wand | Innenwand 1-Schalig | WI-LB | 0 | A | 7.5 | 1213HWa0812968423 | NEW |  | no | 0 | 0 | no | 0 | no | Codetext | AllplanAttributes - Ortscode_Geschoßbezeichnung: E02; W_Deckenanschluss: Gleitender Deckenanschluss Fall 01; ash_W_Trockenbau_Qualitäten: 1b
 | H2 Ebene +2 | WI-LB | 1213Wa 0812970570 |  | Codetext | m² | Trockenbauarbeiten | Wand |  |  | 0 | A | 7.5 | 1213HWa0812968426 | NEW | no | no | 0 | 0 | no | 0 | no | Codetext | AllplanAttributes - Ortscode_Geschoßbezeichnung: E02; W_Deckenanschluss: Gleitender Deckenanschluss Fall 03; ash_W_Trockenbau_Qualitäten: 10a
 | H2 Ebene +2 | WI-LB | 1213Wa 0812970551 |  | Codetext | m² | Trockenbauarbeiten | Wand | Innenwand 1-Schalig | WI-LB | 0 | A | 7.5 | 1213HWa0812968431 | NEW | no | no | REI 60-A1 - D,s2-d0 +A1 | 0 | no | 0 | no | Codetext | AllplanAttributes - Ortscode_Geschoßbezeichnung: E02; W_Deckenanschluss: Gleitender Deckenanschluss Fall 01; ash_W_Trockenbau_Qualitäten: 1b
 | H2 Ebene +2 | WI-STB | 1213Wa 0812969970 | yes | Codetext | m² | Zimmer- und Holzbauarbeiten | Wand | Innenwand 1-Schalig | WI-STB | 0 | A | 7.5 | 1213HWa0812968450 | NEW | yes | no | REI-M 60-A1 | 0 | no | 0 | no | Codetext | AllplanAttributes - Ortscode_Geschoßbezeichnung: E02
 | H2 Ebene +2 | WI-STB | 1213Wa 0812970208 | yes | Codetext | m² | Zimmer- und Holzbauarbeiten | Wand | Innenwand 1-Schalig | WI-STB | 0 | A | 7.5 | 1213HWa0812968451 | NEW | yes | no | REI-M 60-A1 | 0 | no | 0 | no | Codetext | AllplanAttributes - Ortscode_Geschoßbezeichnung: E02
 | H2 Ebene +2 | WI-LB | 1213Wa 0812970452 | yes | Codetext | m² | Trockenbauarbeiten | Wand | Innenwand 1-Schalig | WI-LB | 0 | A | 7.5 | 1213HWa0812968451 | NEW | no | no | REI 60-A1 - D,s2-d0 /A1 | 0 | no | 0 | no | Codetext | AllplanAttributes - Ortscode_Geschoßbezeichnung: E02; ash_W_Trockenbau_Qualitäten: 9
 | H2 Ebene +2 | WI-STB | 1213Wa 0812969974 | yes | Codetext | m² | Zimmer- und Holzbauarbeiten | Wand | Innenwand 1-Schalig | WI-STB | 0 | A | 7.5 | 1213HWa0812968452 | NEW | yes | no | REI-M 60-A1 | 0 | no | 0 | no | Codetext | AllplanAttributes - Ortscode_Geschoßbezeichnung: E02
 | H2 Ebene +2 | WI-LB | 1213Wa 0812970390 | yes | Codetext | m² | Trockenbauarbeiten | Wand | Innenwand 1-Schalig | WI-LB | 0 | A | 7.5 | 1213HWa0812968464 | NEW | no | no | REI 60-A1 - D,s2-d0 /A1 | 0 | no | 0 | no | Codetext | AllplanAttributes - Ortscode_Geschoßbezeichnung: E02; W_Deckenanschluss: Gleitender Deckenanschluss Fall 01; ash_W_Trockenbau_Qualitäten: 13
 | H2 Ebene +2 | WI-LB | 1213Wa 0812969923 | yes | Codetext | m² | Trockenbauarbeiten | Wand | Innenwand 1-Schalig | WI-LB | 0 | A | 7.5 | 1213HWa0812968472 | NEW | no | no | REI 60-A1 - D,s2-d0 /A1 | 0 | no |  | no | Codetext | AllplanAttributes - Ortscode_Geschoßbezeichnung: E02; ash_W_Trockenbau_Qualitäten: 9
 | H2 Ebene +2 | WI-LB | 1213Wa 0812970245 | yes | Codetext | m² | Trockenbauarbeiten | Wand | Innenwand 1-Schalig | WI-LB | 0 | A | 7.5 | 1213HWa0812968480 | NEW |  | no | REI 60-A1 - D,s2-d0 /A1 | 0 | no | 0 | no | Codetext | AllplanAttributes - Ortscode_Geschoßbezeichnung: E02; W_Deckenanschluss: Gleitender Deckenanschluss Fall 01; ash_W_Trockenbau_Qualitäten: 13
 | H2 Ebene +2 | WI-STB | 1213Wa 0812971283 | yes | Codetext | m² | Zimmer- und Holzbauarbeiten | Wand | Außenwand 1-Schalig | WI-STB | 0 | A | 7.5 | 1213HWa0812968520 | NEW | yes | no | REI-M 60-A1 | 0 | no | 0 | no | Codetext | AllplanAttributes - Ortscode_Geschoßbezeichnung: E02
 | H2 Ebene +2 | WI-STB | 1213Wa 0812985985 | yes | Codetext | m² | Zimmer- und Holzbauarbeiten | Wand | Außenwand 1-Schalig | WI-STB | 0 | A | 7.5 | 1213HWa0812969613 | NEW | yes | no | REI-M 60-A1 | 0 | no | 0 | no | Codetext | AllplanAttributes - Ortscode_Geschoßbezeichnung: E02
 | H2 Ebene +2 | WI-STB | 1213Wa 0812971204 | yes |  | m² | Zimmer- und Holzbauarbeiten | Wand | Innenwand 1-Schalig | WI-STB |  |  | 7.5 | 1213HWa0812969833 | NEW | no | no | REI-M 60-A1 | AllplanAttributes - Ortscode_Geschoßbezeichnung: E02
 | H2 Ebene +2 | WI-LB | 1213Wa 0812971179 | yes | Codetext | m² | Trockenbauarbeiten | Wand | Innenwand 1-Schalig | WI-LB | 0 | A | 7.5 | 1213HWa0812971176 | NEW | no | no | REI 60-A1 - D,s2-d0 /A1 | 0 | no | 0 | no | Codetext | AllplanAttributes - Ortscode_Geschoßbezeichnung: E02
 | H2 Ebene +2 | WI-STB | 1213Wa 0812984279 | yes |  | m² | Zimmer- und Holzbauarbeiten | Wand | Innenwand 1-Schalig | WI-STB |  |  | 7.5 | 1213HWa0812971180 | NEW | no | no | REI-M 60-A1 | AllplanAttributes - Ortscode_Geschoßbezeichnung: E02
 | H2 Ebene +2 | WI-HW 60 | 1213Wa 0812970555 | yes |  | m² | Zimmer- und Holzbauarbeiten | Wand | Innenwand 1-Schalig | WI-HW 60 |  |  | 7.5 | 1213HWa0812968144 | NEW | no | no | REI-M 60-D,s2,d0 + A1 |  |  | 47 | AllplanAttributes - Ortscode_Geschoßbezeichnung: E02; ash W_laufende Nr. Statik: 7 (W 6.0-1)
 | H2 Ebene +2 | WI-LB | 1213Wa 0813021739 | yes | Codetext | m² | Trockenbauarbeiten | Wand | Innenwand 1-Schalig | WI-LB | 0 | A | 7.5 | 1213HWa0813021738 | NEW |  | no | 0 | 0 | no | 0 | no | Codetext | AllplanAttributes - Ortscode_Geschoßbezeichnung: E02; W_Deckenanschluss: Gleitender Deckenanschluss Fall 01; ash_W_Trockenbau_Qualitäten: 13
 | H2 Ebene +2 | WI-LB | 1213Wa 0813021751 | yes | Codetext | m² | Trockenbauarbeiten | Wand | Innenwand 1-Schalig | WI-LB | 0 | A | 7.5 | 1213HWa0813021750 | NEW |  | no | 0 | 0 | no | 0 | no | Codetext | AllplanAttributes - Ortscode_Geschoßbezeichnung: E02; W_Deckenanschluss: Gleitender Deckenanschluss Fall 01; ash_W_Trockenbau_Qualitäten: 13
 | H2 Ebene +2 | WI-IW | 1213Wa 0813025687 | yes | Codetext | m² | Trockenbauarbeiten | Wand | Installationswand | WI-IW | 0 | A | 7.5 | 1213HWa0813025686 | NEW |  | no | 0 | 0 | no | 0 | no | Codetext | AllplanAttributes - Ortscode_Geschoßbezeichnung: E02; W_Deckenanschluss: Gleitender Deckenanschluss Fall 01; ash_W_Trockenbau_Qualitäten: 18
2x Gipsfaserplatte | H2 Ebene +2 | WA-LB | 1213Wa 0813026536 | yes |  | m² | Trockenbauarbeiten | Wand | 2x Gipsfaserplatte | WA-LB |  |  | 7.5 | 1213HWa0813026534 | NEW | no | yes | 0 | 0.9 |  | 32 | AllplanAttributes - Ortscode_Geschoßbezeichnung: E02; Sicherheitsklasse: -; Sonnenschutztyp: Movable; g-Wert: 0,51
2x Gipsfaserplatte | H2 Ebene +2 | WA-LB | 1213Wa 0813026537 | yes |  | m² | Trockenbauarbeiten | Wand | 2x Gipsfaserplatte | WA-LB |  |  | 7.5 | 1213HWa0813026534 | NEW | no | yes | 0 | 0.9 |  | 32 | AllplanAttributes - Ortscode_Geschoßbezeichnung: E02; Sicherheitsklasse: -; Sonnenschutztyp: Movable; g-Wert: 0,51
 | H2 Ebene +2 | WI-HW 60 | 1213Wa 0812986144 | yes | Codetext | m² | Zimmer- und Holzbauarbeiten | Wand | Innenwand 1-Schalig | WI-HW 60 | 0 | A | 7.5 | 1213HWa0812968142 | NEW | yes | no | REI 60-A1 - D,s2-d0 /A1 | 0 | no | 0 | no | Codetext | AllplanAttributes - Ortscode_Geschoßbezeichnung: E02; ash W_laufende Nr. Statik: 1 (W 1.0/ 1.1/ 1.2)
 | H2 Ebene +2 | WI-LB | 1213Wa 0813057764 | yes | Codetext | m² | Trockenbauarbeiten | Wand | Innenwand 1-Schalig | WI-LB | 0 | A | 7.5 | 1213HWa0813057753 | NEW | no | no | 0 | 0 | no | 47 | no | Codetext | AllplanAttributes - Ortscode_Geschoßbezeichnung: E02; W_Deckenanschluss: Gleitender Deckenanschluss Fall 03; ash_W_Trockenbau_Qualitäten: 1b
 | H2 Ebene +2 | WI-LB | 1213Wa 0812986089 | yes | Codetext | m² | Trockenbauarbeiten | Wand | Innenwand 1-Schalig | WI-LB | 0 | A | 7.5 | 1213HWa0812968203 | NEW | no | no | REI 60-A1 - D,s2-d0 /A1 | 0 | no | 0 | no | Codetext | AllplanAttributes - Ortscode_Geschoßbezeichnung: E02; W_Deckenanschluss: Gleitender Deckenanschluss Fall 01; ash_W_Trockenbau_Qualitäten: 1b
 | H2 Ebene +2 | WI-GKF | 1213Wa 0812970109 | yes | Codetext | m² | Trockenbauarbeiten | Wand | "BS-Beplankung; 2-fach Gipsfaserplatten" | WI-GKF | 0 | A | 7.5 | 1213HWa0812969681 | NEW | no | no | EI 60-A1 - D,s2,d0 +A1 | 0 | no | 0 | no | Codetext | AllplanAttributes - Ortscode_Geschoßbezeichnung: E02
 | H2 Ebene +2 | WI-GKF | 1213Wa 0812970086 | yes | Codetext | m² | Trockenbauarbeiten | Wand | "BS-Beplankung; 2-fach Gipsfaserplatten" | WI-GKF | 0 | A | 7.5 | 1213HWa0812969720 | NEW | no | no | EI 60-A1 - D,s2,d0 +A1 | 0 | no | 0 | no | Codetext | AllplanAttributes - Ortscode_Geschoßbezeichnung: E02
 | H2 Ebene +2 | WI-GKF | 1213Wa 0812970114 | yes | Codetext | m² | Trockenbauarbeiten | Wand | "BS-Beplankung; 2-fach Gipsfaserplatten" | WI-GKF | 0 | A | 7.5 | 1213HWa0812969677 | NEW | no | no | EI 60-A1 - D,s2,d0 +A1 | 0 | no | 0 | no | Codetext | AllplanAttributes - Ortscode_Geschoßbezeichnung: E02
 | H2 Ebene +2 | WI-GKF | 1213Wa 0813116661 | yes | Codetext | m² | Trockenbauarbeiten | Wand | "BS-Beplankung; 2-fach Gipsfaserplatten" | WI-GKF | 0 | A | 7.5 | 1213HWa0813116659 | NEW | no | no | EI 60-A1 - D,s2,d0 +A1 | 0 | no | 0 | no | Codetext | AllplanAttributes - Ortscode_Geschoßbezeichnung: E02
 | H2 Ebene +2 | WI-GKF | 1213Wa 0812970125 | yes | Codetext | m² | Trockenbauarbeiten | Wand | "BS-Beplankung; 2-fach Gipsfaserplatten" | WI-GKF | 0 | A | 7.5 | 1213HWa0812969680 | NEW | no | no | EI 60-A1 - D,s2,d0 +A1 | 0 | no | 0 | no | Codetext | AllplanAttributes - Ortscode_Geschoßbezeichnung: E02
 | H2 Ebene +2 | WI-GKF | 1213Wa 0812970075 | yes | Codetext | m² | Trockenbauarbeiten | Wand | "BS-Beplankung; 2-fach Gipsfaserplatten" | WI-GKF | 0 | A | 7.5 | 1213HWa0812969725 | NEW | no | no | EI 60-A1 - D,s2,d0 +A1 | 0 | no | 0 | no | Codetext | AllplanAttributes - Ortscode_Geschoßbezeichnung: E02
 | H2 Ebene +2 | WI-GKF | 1213Wa 0813116545 | yes | Codetext | m² | Trockenbauarbeiten | Wand | "BS-Beplankung; 2-fach Gipsfaserplatten" | WI-GKF | 0 | A | 7.5 | 1213HWa0813116543 | NEW | no | no | EI 60-A1 - D,s2,d0 +A1 | 0 | no | 0 | no | Codetext | AllplanAttributes - Ortscode_Geschoßbezeichnung: E02
 | H2 Ebene +2 | WI-GKF | 1213Wa 0812970118 | yes | Codetext | m² | Trockenbauarbeiten | Wand | "BS-Beplankung; 2-fach Gipsfaserplatten" | WI-GKF | 0 | A | 7.5 | 1213HWa0812969679 | NEW | no | no | EI 60-A1 - D,s2,d0 +A1 | 0 | no | 0 | no | Codetext | AllplanAttributes - Ortscode_Geschoßbezeichnung: E02
 | H2 Ebene +2 | WI-GKF | 1213Wa 0812970092 | yes | Codetext | m² | Trockenbauarbeiten | Wand | "BS-Beplankung; 2-fach Gipsfaserplatten" | WI-GKF | 0 | A | 7.5 | 1213HWa0812968380 | NEW | no | no | EI 60-A1 - D,s2,d0 +A1 | 0 | no | 0 | no | Codetext | AllplanAttributes - Ortscode_Geschoßbezeichnung: E02
 | H2 Ebene +2 | WI-GKF | 1213Wa 0812970107 | yes | Codetext | m² | Trockenbauarbeiten | Wand | "BS-Beplankung; 2-fach Gipsfaserplatten" | WI-GKF | 0 | A | 7.5 | 1213HWa0812968273 | NEW | no | no | EI 60-A1 - D,s2,d0 +A1 | 0 | no | 0 | no | Codetext | AllplanAttributes - Ortscode_Geschoßbezeichnung: E02
 | H2 Ebene +2 | WI-LW 60 | 1213Wa 0813187688 | yes | Codetext | m² | Trockenbauarbeiten | Wand | Innenwand 1-Schalig | WI-LW 60 | 0 | A | 7.5 | 1213HWa0813187679 | NEW | no | no | REI 60-A1 - D,s2-d0 +A1 | 0 | no | 47 | no | Codetext | AllplanAttributes - Ortscode_Geschoßbezeichnung: E02; W_Deckenanschluss: Gleitender Deckenanschluss Fall 01; ash_W_Trockenbau_Qualitäten: 12b; Sicherheitsklasse: -
 | H2 Ebene +2 | WI-HW 60 | 1213Wa 0812970316 | yes | Codetext | m² | Zimmer- und Holzbauarbeiten | Wand | Innenwand 1-Schalig | WI-HW 60 | 0 | A | 7.5 | 1213HWa0812968293 | NEW | yes | no | REI 60-A1 - D,s2-d0 +A1 | 0 | no | 0 | no | Codetext | AllplanAttributes - Ortscode_Geschoßbezeichnung: E02; ash W_laufende Nr. Statik: 3 (W 3.0)
 | H2 Ebene +2 | WI-HW 60 | 1213Wa 0813246062 | yes | Codetext | m² | Zimmer- und Holzbauarbeiten | Wand | Innenwand 1-Schalig | WI-HW 60 | 0 | A | 7.5 | 1213HWa0812968166 | NEW |  | no | 0 | 0 | no |  | no | Codetext | AllplanAttributes - Ortscode_Geschoßbezeichnung: E02; Sicherheitsklasse: -; ash W_laufende Nr. Statik: 1 (W 1.0/ 1.1/ 1.2)
 | H2 Ebene +2 | WI-IW | 1213Wa 0813063722 | yes | Codetext | m² | Trockenbauarbeiten | Wand | Installationswand | WI-IW | 0 | A | 7.5 | 1213HWa0813063721 | NEW |  | no | 0 | 0 | no | 52 | no | Codetext | AllplanAttributes - Ortscode_Geschoßbezeichnung: E02; ash_W_Trockenbau_Qualitäten: 6
 | H2 Ebene +2 | WI-IW | 1213Wa 0813062758 | yes | Codetext | m² | Trockenbauarbeiten | Wand | Installationswand | WI-IW | 0 | A | 7.5 | 1213HWa0813062757 | NEW |  | no | 0 | 0 | no | 52 | no | Codetext | AllplanAttributes - Ortscode_Geschoßbezeichnung: E02; ash_W_Trockenbau_Qualitäten: 6
 | H2 Ebene +2 | WI-HW 60 | 1213Wa 0813220545 | yes | Codetext | m² | Zimmer- und Holzbauarbeiten | Wand | Innenwand 1-Schalig | WI-HW 60 | 0 | A | 7.5 | 1213HWa0813122257 | NEW |  | no | REI 60-A1 - D,s2-d0 +A1 | 0 | no | 0 | no | Codetext | AllplanAttributes - Ortscode_Geschoßbezeichnung: E02; Sicherheitsklasse: -; ash W_laufende Nr. Statik: 3 (W 3.0)
 | H2 Ebene +2 | WI-LB | 1213Wa 0812970257 | yes | Codetext | m² | Trockenbauarbeiten | Wand | Innenwand 1-Schalig | WI-LB | 0 | A | 7.5 | 1213HWa0812968498 | NEW | no | no | REI 60-A1 - D,s2-d0 /A1 | 0 | no |  | no | Codetext | AllplanAttributes - Ortscode_Geschoßbezeichnung: E02; ash_W_Trockenbau_Qualitäten: 9
 | H2 Ebene +2 | WI-LB | 1213Wa 0812986157 | yes | Codetext | m² | Trockenbauarbeiten | Wand | Innenwand 1-Schalig | WI-LB | 0 | A | 7.5 | 1213HWa0812968506 | NEW |  | no | REI 60-A1 - D,s2-d0 +A1 | 0 | no | 52 | no | Codetext | AllplanAttributes - Ortscode_Geschoßbezeichnung: E02; W_Deckenanschluss: Gleitender Deckenanschluss Fall 01; ash_W_Trockenbau_Qualitäten: 4
 | H2 Ebene +2 | WI-HW 60 | 1213Wa 0812985936 | yes | Codetext | m² | Zimmer- und Holzbauarbeiten | Wand | Innenwand 1-Schalig | WI-HW 60 | 0 | A | 7.5 | 1213HWa0812968135 | NEW |  | no | REI 60-A1 - D,s2-d0 +A1 | 0 | no | 0 | no | Codetext | AllplanAttributes - Ortscode_Geschoßbezeichnung: E02; ash W_laufende Nr. Statik: 3 (W 3.0)
 | H2 Ebene +2 | WI-HW 60 | 1213Wa 0812970322 | yes |  | m² | Zimmer- und Holzbauarbeiten | Wand | Innenwand 1-Schalig | WI-HW 60 |  |  | 7.5 | 1213HWa0812968271 | NEW | no | no | REI-M 60-D,s2,d0 + A1 | AllplanAttributes - Ortscode_Geschoßbezeichnung: E02; ash W_laufende Nr. Statik: 7 (W 6.0-1)
 | H2 Ebene +2 | WA-STB | 1213Wa 0812986440 | yes | Codetext | m² | Zimmer- und Holzbauarbeiten | Wand | Außenwand 1-Schalig | WA-STB | 0 | A | 7.5 | 1213HWa0812971318 | NEW | yes | no | REI-M 60-A1 | 0 | no | 0 | no | Codetext | AllplanAttributes - Ortscode_Geschoßbezeichnung: E02
 | H2 Ebene +2 | WI-STB | 1213Wa 0812985887 | yes | Codetext | m² | Zimmer- und Holzbauarbeiten | Wand | Innenwand 1-Schalig | WI-STB | 0 | A | 7.5 | 1213HWa0812968545 | NEW | yes | no | REI 60-A1 - D,s2-d0 /A1 | 0 | no | 0 | no | Codetext | AllplanAttributes - Ortscode_Geschoßbezeichnung: E02
 | H2 Ebene +2 | WI-LB | 1213Wa 0812985893 | yes | Codetext | m² | Trockenbauarbeiten | Wand | Innenwand 1-Schalig | WI-LB | 0 | A | 7.5 | 1213HWa0812984275 | NEW | no | no | 0 | 0 | no | 0 | no | Codetext | AllplanAttributes - Ortscode_Geschoßbezeichnung: E02; W_Deckenanschluss: Gleitender Deckenanschluss Fall 01
 | H2 Ebene +2 | WI-STB | 1213Wa 0812969950 | yes | Codetext | m² | Zimmer- und Holzbauarbeiten | Wand | Außenwand 1-Schalig | WI-STB | 0 | A | 7.5 | 1213HWa0812968278 | NEW | yes | no | REI 60-A1 - D,s2-d0 /A1 | 0 | no | 0 | no | Codetext | AllplanAttributes - Ortscode_Geschoßbezeichnung: E02
 | H2 Ebene +2 | WI-STB | 1213Wa 0812969926 | yes | Codetext | m² | Zimmer- und Holzbauarbeiten | Wand | Außenwand 1-Schalig | WI-STB | 0 | A | 7.5 | 1213HWa0812968075 | NEW | yes | no | REI 60-A1 - D,s2-d0 /A1 | 0 | no | 0 | no | Codetext | AllplanAttributes - Ortscode_Geschoßbezeichnung: E02
 | H2 Ebene +2 | WI-STB | 1213Wa 0812970374 | yes | Codetext | m² | Zimmer- und Holzbauarbeiten | Wand | Außenwand 1-Schalig | WI-STB | 0 | A | 7.5 | 1213HWa0812968066 | NEW | yes | no | REI 60-A1 - D,s2-d0 /A1 | 0 | no | 52 | no | Codetext | AllplanAttributes - Ortscode_Geschoßbezeichnung: E02
 | H2 Ebene +2 | WI-STB | 1213Wa 0812970528 | yes | Codetext | m² | Zimmer- und Holzbauarbeiten | Wand | Außenwand 1-Schalig | WI-STB | 0 | A | 7.5 | 1213HWa0812968067 | NEW | yes | no | REI 60-A1 - D,s2-d0 /A1 | 0 | no | 52 | no | Codetext | AllplanAttributes - Ortscode_Geschoßbezeichnung: E02
 | H2 Ebene +2 | WI-STB | 1213Wa 0812970385 | yes | Codetext | m² | Zimmer- und Holzbauarbeiten | Wand | Außenwand 1-Schalig | WI-STB | 0 | A | 7.5 | 1213HWa0812968073 | NEW | yes | no | REI 60-A1 - D,s2-d0 /A1 | 0 | no | 47 | no | Codetext | AllplanAttributes - Ortscode_Geschoßbezeichnung: E02
 | H2 Ebene +2 | WI-STB | 1213Wa 0812970536 | yes | Codetext | m² | Zimmer- und Holzbauarbeiten | Wand | Außenwand 1-Schalig | WI-STB | 0 | A | 7.5 | 1213HWa0812968074 | NEW | yes | no | REI 60-A1 - D,s2-d0 /A1 | 0 | no | 47 | no | Codetext | AllplanAttributes - Ortscode_Geschoßbezeichnung: E02
 | H2 Ebene +2 | WI-LB | 1213Wa 0812970919 |  | Codetext | m² | Trockenbauarbeiten | Wand |  |  | 0 | A | 7.5 | 1213HWa0812968036 | NEW |  | no | 0 | 0 | no | 47 | no | Codetext | AllplanAttributes - Ortscode_Geschoßbezeichnung: E02; W_Deckenanschluss: Gleitender Deckenanschluss Fall 03; ash_W_Trockenbau_Qualitäten: 1c
 | H2 Ebene +2 | WI-LB | 1213Wa 0812970916 |  | Codetext | m² | Trockenbauarbeiten | Wand |  |  | 0 | A | 7.5 | 1213HWa0812968037 | NEW |  | no | 0 | 0 | no | 47 | no | Codetext | AllplanAttributes - Ortscode_Geschoßbezeichnung: E02; W_Deckenanschluss: Gleitender Deckenanschluss Fall 03; ash_W_Trockenbau_Qualitäten: 1c
 | H2 Ebene +2 | WI-LB | 1213Wa 0812970913 |  | Codetext | m² | Trockenbauarbeiten | Wand |  |  | 0 | A | 7.5 | 1213HWa0812968038 | NEW |  | no | 0 | 0 | no | 47 | no | Codetext | AllplanAttributes - Ortscode_Geschoßbezeichnung: E02; W_Deckenanschluss: Gleitender Deckenanschluss Fall 03; ash_W_Trockenbau_Qualitäten: 1c
 | H2 Ebene +2 | WI-LB | 1213Wa 0812971252 |  | Codetext | m² | Trockenbauarbeiten | Wand | Innenwand 1-Schalig | WI-LB | 0 | A | 7.5 | 1213HWa0812968039 | NEW |  | no | REI 30 | 0 | no | 47 | no | Codetext | AllplanAttributes - Ortscode_Geschoßbezeichnung: E02; W_Deckenanschluss: Gleitender Deckenanschluss Fall 03; ash_W_Trockenbau_Qualitäten: 1c
 | H2 Ebene +2 | WI-LB | 1213Wa 0812971256 |  | Codetext | m² | Trockenbauarbeiten | Wand | Innenwand 1-Schalig | WI-LB | 0 | A | 7.5 | 1213HWa0812968040 | NEW |  | no | REI 30 | 0 | no | 47 | no | Codetext | AllplanAttributes - Ortscode_Geschoßbezeichnung: E02; W_Deckenanschluss: Gleitender Deckenanschluss Fall 03; ash_W_Trockenbau_Qualitäten: 1c
 | H2 Ebene +2 | WI-LB | 1213Wa 0812970612 |  | Codetext | m² | Trockenbauarbeiten | Wand | Innenwand 1-Schalig | WI-LB | 0 | A | 7.5 | 1213HWa0812968041 | NEW |  | no | REI 30 | 0 | no | 47 | no | Codetext | AllplanAttributes - Ortscode_Geschoßbezeichnung: E02; W_Deckenanschluss: Gleitender Deckenanschluss Fall 03; ash_W_Trockenbau_Qualitäten: 1c
 | H2 Ebene +2 | WI-LB | 1213Wa 0812970699 |  | Codetext | m² | Trockenbauarbeiten | Wand |  |  | 0 | A | 7.5 | 1213HWa0812968042 | NEW |  | no | 0 | 0 | no | 47 | no | Codetext | AllplanAttributes - Ortscode_Geschoßbezeichnung: E02; W_Deckenanschluss: Gleitender Deckenanschluss Fall 03; ash_W_Trockenbau_Qualitäten: 1c
 | H2 Ebene +2 | WI-STB | 1213Wa 0812970340 | yes | Codetext | m² | Zimmer- und Holzbauarbeiten | Wand | Außenwand 1-Schalig | WI-STB | 0 | A | 7.5 | 1213HWa0812968068 | NEW | yes | no | REI 60-A1 - D,s2-d0 /A1 | 0 | no | 52 | no | Codetext | AllplanAttributes - Ortscode_Geschoßbezeichnung: E02
 | H2 Ebene +2 | WI-LB | 1213Wa 0812970579 |  | Codetext | m² | Trockenbauarbeiten | Wand | Innenwand 1-Schalig | WI-LB | 0 | A | 7.5 | 1213HWa0812968083 | NEW |  | no | REI 30 | 0 | no | 47 | no | Codetext | AllplanAttributes - Ortscode_Geschoßbezeichnung: E02; W_Deckenanschluss: Gleitender Deckenanschluss Fall 03; ash_W_Trockenbau_Qualitäten: 1c
 | H2 Ebene +2 | WI-LB | 1213Wa 0812970561 |  | Codetext | m² | Trockenbauarbeiten | Wand | Innenwand 1-Schalig | WI-LB | 0 | A | 7.5 | 1213HWa0812968087 | NEW |  | no | REI 30 | 0 | no | 47 | no | Codetext | AllplanAttributes - Ortscode_Geschoßbezeichnung: E02; W_Deckenanschluss: Gleitender Deckenanschluss Fall 03; ash_W_Trockenbau_Qualitäten: 1c
 | H2 Ebene +2 | WI-LB | 1213Wa 0812970690 |  | Codetext | m² | Trockenbauarbeiten | Wand |  |  | 0 | A | 7.5 | 1213HWa0812968088 | NEW |  | no | 0 | 0 | no | 47 | no | Codetext | AllplanAttributes - Ortscode_Geschoßbezeichnung: E02; W_Deckenanschluss: Gleitender Deckenanschluss Fall 03; ash_W_Trockenbau_Qualitäten: 1c
 | H2 Ebene +2 | WI-LB | 1213Wa 0812970753 |  | Codetext | m² | Trockenbauarbeiten | Wand | Innenwand 1-Schalig | WI-LB | 0 | A | 7.5 | 1213HWa0812968089 | NEW |  | no | REI 30 | 0 | no | 47 | no | Codetext | AllplanAttributes - Ortscode_Geschoßbezeichnung: E02; W_Deckenanschluss: Gleitender Deckenanschluss Fall 03; ash_W_Trockenbau_Qualitäten: 1c
 | H2 Ebene +2 | WI-LB | 1213Wa 0812970706 |  | Codetext | m² | Trockenbauarbeiten | Wand |  |  | 0 | A | 7.5 | 1213HWa0812968090 | NEW |  | no | 0 | 0 | no | 47 | no | Codetext | AllplanAttributes - Ortscode_Geschoßbezeichnung: E02; W_Deckenanschluss: Gleitender Deckenanschluss Fall 03; ash_W_Trockenbau_Qualitäten: 1c
 | H2 Ebene +2 | WI-LB | 1213Wa 0812970902 |  | Codetext | m² | Trockenbauarbeiten | Wand | Innenwand 1-Schalig | WI-LB | 0 | A | 7.5 | 1213HWa0812968092 | NEW |  | no | REI 30 | 0 | no | 47 | no | Codetext | AllplanAttributes - Ortscode_Geschoßbezeichnung: E02; W_Deckenanschluss: Gleitender Deckenanschluss Fall 03; ash_W_Trockenbau_Qualitäten: 1c
 | H2 Ebene +2 | WI-LB | 1213Wa 0812970875 |  | Codetext | m² | Trockenbauarbeiten | Wand | Innenwand 1-Schalig | WI-LB | 0 | A | 7.5 | 1213HWa0812968093 | NEW |  | no | REI 30 | 0 | no | 47 | no | Codetext | AllplanAttributes - Ortscode_Geschoßbezeichnung: E02; W_Deckenanschluss: Gleitender Deckenanschluss Fall 03; ash_W_Trockenbau_Qualitäten: 1c
 | H2 Ebene +2 | WI-LB | 1213Wa 0812970872 |  | Codetext | m² | Trockenbauarbeiten | Wand | Innenwand 1-Schalig | WI-LB | 0 | A | 7.5 | 1213HWa0812968094 | NEW |  | no | REI 30 | 0 | no | 47 | no | Codetext | AllplanAttributes - Ortscode_Geschoßbezeichnung: E02; W_Deckenanschluss: Gleitender Deckenanschluss Fall 03; ash_W_Trockenbau_Qualitäten: 1c
 | H2 Ebene +2 | WI-LB | 1213Wa 0812986161 | yes | Codetext | m² | Trockenbauarbeiten | Wand | Innenwand 1-Schalig | WI-LB | 0 | A | 7.5 | 1213HWa0812968497 | NEW |  | no | 0 | 0 | no | 52 | no | Codetext | AllplanAttributes - Ortscode_Geschoßbezeichnung: E02; W_Deckenanschluss: Gleitender Deckenanschluss Fall 01; ash_W_Trockenbau_Qualitäten: 4
 | H2 Ebene +2 | WI-LB | 1213Wa 0812969888 | yes | Codetext | m² | Trockenbauarbeiten | Wand | Innenwand 1-Schalig | WI-LB | 0 | A | 7.5 | 1213HWa0812969866 | NEW | no | no | 0 | 0 | no | 42 | no | Codetext | AllplanAttributes - Ortscode_Geschoßbezeichnung: E02; W_Deckenanschluss: Gleitender Deckenanschluss Fall 03; ash_W_Trockenbau_Qualitäten: 1b
 | H2 Ebene +2 | WI-HW 60 | 1213Wa 0812986396 | yes | Codetext | m² | Zimmer- und Holzbauarbeiten | Wand | Innenwand 1-Schalig | WI-HW 60 | 0 | A | 7.5 | 1213HWa0812968161 | NEW | yes | no | REI 60-A1 - D,s2-d0 +A1 | 0 | no | 52 | no | Codetext | AllplanAttributes - Ortscode_Geschoßbezeichnung: E02; ash W_laufende Nr. Statik: 7 (W 6.0-1)
 | H2 Ebene +2 | WI-HW 60 | 1213Wa 0812971207 | yes |  | m² | Zimmer- und Holzbauarbeiten | Wand | Innenwand 1-Schalig | WI-HW 60 |  |  | 7.5 | 1213HWa0812969831 | NEW | no | no | REI-M 60-D,s2,d0 + A1 |  |  | 42 | AllplanAttributes - Ortscode_Geschoßbezeichnung: E02; ash W_laufende Nr. Statik: 7 (W 6.0-1)
 | H2 Ebene +2 | WI-LB | 1213Wa 0812970939 | yes | Codetext | m² | Trockenbauarbeiten | Wand | Innenwand 1-Schalig | WI-LB | 0 | A | 7.5 | 1213HWa0812968052 | NEW |  | no | 0 | 0 | no | 47 | no | Codetext | AllplanAttributes - Ortscode_Geschoßbezeichnung: E02; W_Deckenanschluss: Gleitender Deckenanschluss Fall 01; ash_W_Trockenbau_Qualitäten: 1b
 | H2 Ebene +2 | WI-LB | 1213Wa 0812986036 | yes | Codetext | m² | Trockenbauarbeiten | Wand | Innenwand 1-Schalig | WI-LB | 0 | A | 7.5 | 1213HWa0812968204 | NEW | no | no | REI 60-A1 - D,s2-d0 +A1 | 0 | no | 47 | no | Codetext | AllplanAttributes - Ortscode_Geschoßbezeichnung: E02; W_Deckenanschluss: Gleitender Deckenanschluss Fall 01; ash_W_Trockenbau_Qualitäten: 1b
 | H2 Ebene +2 | WI-STB | 1213Wa 0812970406 | yes | Codetext | m² | Zimmer- und Holzbauarbeiten | Wand | Außenwand 1-Schalig | WI-STB | 0 | A | 7.5 | 1213HWa0812968077 | NEW | yes | no | REI 60-A1 - D,s2-d0 /A1 | 0 | no | 52 | no | Codetext | AllplanAttributes - Ortscode_Geschoßbezeichnung: E02
 | H2 Ebene +2 | WI-STB | 1213Wa 0812970351 | yes | Codetext | m² | Zimmer- und Holzbauarbeiten | Wand | Außenwand 1-Schalig | WI-STB | 0 | A | 7.5 | 1213HWa0812968078 | NEW | yes | no | REI 60-A1 - D,s2-d0 /A1 | 0 | no | 52 | no | Codetext | AllplanAttributes - Ortscode_Geschoßbezeichnung: E02
 | H2 Ebene +2 | WI-LB | 1213Wa 0812970782 | yes | Codetext | m² | Trockenbauarbeiten | Wand | Innenwand 1-Schalig | WI-LB | 0 | A | 7.5 | 1213HWa0812968290 | NEW |  | no | REI 60-A1 - D,s2-d0 +A1 | 0 | no | 47 | no | Codetext | AllplanAttributes - Ortscode_Geschoßbezeichnung: E02; W_Deckenanschluss: Gleitender Deckenanschluss Fall 01; ash_W_Trockenbau_Qualitäten: 1b
 | H2 Ebene +2 | WI-LB | 1213Wa 0812970734 | yes | Codetext | m² | Trockenbauarbeiten | Wand | Innenwand 1-Schalig | WI-LB | 0 | A | 7.5 | 1213HWa0812968051 | NEW |  | no | 0 | 0 | no | 47 | no | Codetext | AllplanAttributes - Ortscode_Geschoßbezeichnung: E02; W_Deckenanschluss: Gleitender Deckenanschluss Fall 01; ash_W_Trockenbau_Qualitäten: 1b
 | H2 Ebene +2 | WI-LB | 1213Wa 0812970724 | yes | Codetext | m² | Trockenbauarbeiten | Wand | Innenwand 1-Schalig | WI-LB | 0 | A | 7.5 | 1213HWa0812968053 | NEW |  | no | 0 | 0 | no | 47 | no | Codetext | AllplanAttributes - Ortscode_Geschoßbezeichnung: E02; W_Deckenanschluss: Gleitender Deckenanschluss Fall 01; ash_W_Trockenbau_Qualitäten: 1b
 | H2 Ebene +2 | WI-LB | 1213Wa 0812970721 | yes | Codetext | m² | Trockenbauarbeiten | Wand | Innenwand 1-Schalig | WI-LB | 0 | A | 7.5 | 1213HWa0812968121 | NEW | no | no | 0 | 0 | no | 47 | no | Codetext | AllplanAttributes - Ortscode_Geschoßbezeichnung: E02; W_Deckenanschluss: Gleitender Deckenanschluss Fall 01; ash_W_Trockenbau_Qualitäten: 1b
 | H2 Ebene +2 | WI-LB | 1213Wa 0812970934 | yes | Codetext | m² | Trockenbauarbeiten | Wand | Innenwand 1-Schalig | WI-LB | 0 | A | 7.5 | 1213HWa0812968082 | NEW |  | no | 0 | 0 | no | 47 | no | Codetext | AllplanAttributes - Ortscode_Geschoßbezeichnung: E02; W_Deckenanschluss: Gleitender Deckenanschluss Fall 01; ash_W_Trockenbau_Qualitäten: 1b
 | H2 Ebene +2 | WI-LB | 1213Wa 0812986000 | yes | Codetext | m² | Trockenbauarbeiten | Wand | Innenwand 1-Schalig | WI-LB | 0 | A | 7.5 | 1213HWa0812968035 | NEW | no | no | 0 | 0 | no | 47 | no | Codetext | AllplanAttributes - Ortscode_Geschoßbezeichnung: E02; W_Deckenanschluss: Gleitender Deckenanschluss Fall 01; ash_W_Trockenbau_Qualitäten: 1b
 | H2 Ebene +2 | WI-HW 60 | 1213Wa 0812986059 | yes | Codetext | m² | Zimmer- und Holzbauarbeiten | Wand | Innenwand 1-Schalig | WI-HW 60 | 0 | A | 7.5 | 1213HWa0812968130 | NEW | no | no | REI 60-A1 - D,s2-d0 +A1 | 0 | no | 47 | no | Codetext | AllplanAttributes - Ortscode_Geschoßbezeichnung: E02; Sicherheitsklasse: -; ash W_laufende Nr. Statik: 3 (W 3.0)
 | H2 Ebene +2 | WI-LB | 1213Wa 0813088785 | yes | Codetext | m² | Trockenbauarbeiten | Wand | Innenwand 1-Schalig | WI-LB | 0 | A | 7.5 | 1213HWa0812968130 | NEW | no | no | REI 60-A1 - D,s2-d0 /A1 | 0 | no | 47 | no | Codetext | AllplanAttributes - Ortscode_Geschoßbezeichnung: E02; ash_W_Trockenbau_Qualitäten: 6; Sicherheitsklasse: -
 | H2 Ebene +2 | WI-HW 60 | 1213Wa 0812970538 | yes | Codetext | m² | Zimmer- und Holzbauarbeiten | Wand | Innenwand 1-Schalig | WI-HW 60 | 0 | A | 7.5 | 1213HWa0812968131 | NEW |  | no | 0 | 0 | no | 47 | no | Codetext | AllplanAttributes - Ortscode_Geschoßbezeichnung: E02; Sicherheitsklasse: -; ash W_laufende Nr. Statik: 3 (W 3.0)
 | H2 Ebene +2 | WI-LB | 1213Wa 0813088980 | yes | Codetext | m² | Trockenbauarbeiten | Wand | Innenwand 1-Schalig | WI-LB | 0 | A | 7.5 | 1213HWa0812968131 | NEW |  | no | 0 | 0 | no | 47 | no | Codetext | AllplanAttributes - Ortscode_Geschoßbezeichnung: E02; ash_W_Trockenbau_Qualitäten: 6; Sicherheitsklasse: -
 | H2 Ebene +2 | WI-STB | 1213Wa 0812970328 | yes | Codetext | m² | Zimmer- und Holzbauarbeiten | Wand | Außenwand 1-Schalig | WI-STB | 0 | A | 7.5 | 1213HWa0812968070 | NEW | yes | no | REI 60-A1 - D,s2-d0 /A1 | 0 | no | 47 | no | Codetext | AllplanAttributes - Ortscode_Geschoßbezeichnung: E02
 | H2 Ebene +2 | WI-LB | 1213Wa 0812986450 | yes | Codetext | m² | Trockenbauarbeiten | Wand | Innenwand 1-Schalig | WI-LB | 0 | A | 7.5 | 1213HWa0812971322 | NEW |  | no | 0 | 0 | no | 52 | no | Codetext | AllplanAttributes - Ortscode_Geschoßbezeichnung: E02; W_Deckenanschluss: Gleitender Deckenanschluss Fall 01; ash_W_Trockenbau_Qualitäten: 1b
 | H2 Ebene +2 | WI-LB | 1213Wa 0812986446 | yes | Codetext | m² | Trockenbauarbeiten | Wand | Innenwand 1-Schalig | WI-LB | 0 | A | 7.5 | 1213HWa0812971324 | NEW |  | no | 0 | 0 | no | 52 | no | Codetext | AllplanAttributes - Ortscode_Geschoßbezeichnung: E02; W_Deckenanschluss: Gleitender Deckenanschluss Fall 01; ash_W_Trockenbau_Qualitäten: 1b
 | H2 Ebene +2 | WI-HW 60 | 1213Wa 0812970776 | yes | Codetext | m² | Zimmer- und Holzbauarbeiten | Wand | Innenwand 1-Schalig | WI-HW 60 | 0 | A | 7.5 | 1213HWa0812968169 | NEW | no | no | 0 | 0 | no | 52 | no | Codetext | AllplanAttributes - Ortscode_Geschoßbezeichnung: E02; Sicherheitsklasse: -; ash W_laufende Nr. Statik: 3 (W 3.0)
 | H2 Ebene +2 | Installationsraum | 1213Wa 0813085585 | yes | Codetext | m² | Trockenbauarbeiten | Wand | Innenwand 1-Schalig | Installationsraum | 0 | A | 7.5 | 1213HWa0812968169 | NEW | no | no | 0 | 0 | no | 0 | no | Codetext | AllplanAttributes - Ortscode_Geschoßbezeichnung: E02; Sicherheitsklasse: -
 | H2 Ebene +2 | WI-LB | 1213Wa 0813195916 | yes | Codetext | m² | Trockenbauarbeiten | Wand | Innenwand 1-Schalig | WI-LB | 0 | A | 7.5 | 1213HWa0812968169 | NEW | no | no | 0 | 0 | no | 52 | no | Codetext | AllplanAttributes - Ortscode_Geschoßbezeichnung: E02; ash_W_Trockenbau_Qualitäten: 8; Sicherheitsklasse: -
 | H2 Ebene +2 | WI-HW 60 | 1213Wa 0813342384 | yes | Codetext | m² | Zimmer- und Holzbauarbeiten | Wand | Innenwand 1-Schalig | WI-HW 60 | 0 | A | 7.5 | 1213HWa0812968168 | NEW | no | no | REI 60-A1 - D,s2-d0 +A1 | 0 | no | 52 | no | Codetext | AllplanAttributes - Ortscode_Geschoßbezeichnung: E02; Sicherheitsklasse: -; ash W_laufende Nr. Statik: 3 (W 3.0)
 | H2 Ebene +2 | Installationsraum | 1213Wa 0813342382 | yes | Codetext | m² | Trockenbauarbeiten | Wand | Innenwand 1-Schalig | Installationsraum | 0 | A | 7.5 | 1213HWa0812968168 | NEW | no | no | 0 | 0 | no | 0 | no | Codetext | AllplanAttributes - Ortscode_Geschoßbezeichnung: E02; Sicherheitsklasse: -
 | H2 Ebene +2 | WI-LB | 1213Wa 0813342381 | yes | Codetext | m² | Trockenbauarbeiten | Wand | Innenwand 1-Schalig | WI-LB | 0 | A | 7.5 | 1213HWa0812968168 | NEW | no | no | REI 60-A1 - D,s2-d0 /A1 | 0 | no | 52 | no | Codetext | AllplanAttributes - Ortscode_Geschoßbezeichnung: E02; ash_W_Trockenbau_Qualitäten: 6; Sicherheitsklasse: -
 | H2 Ebene +2 | WI-HW 60 | 1213Wa 0812986072 | yes | Codetext | m² | Zimmer- und Holzbauarbeiten | Wand | Innenwand 1-Schalig | WI-HW 60 | 0 | A | 7.5 | 1213HWa0812968366 | NEW | no | no | REI 60-A1 - D,s2-d0 +A1 | 0 | no | 47 | no | Codetext | AllplanAttributes - Ortscode_Geschoßbezeichnung: E02; Sicherheitsklasse: -; ash W_laufende Nr. Statik: 3 (W 3.0)
 | H2 Ebene +2 | Installationsraum | 1213Wa 0813083945 | yes | Codetext | m² | Trockenbauarbeiten | Wand | Innenwand 1-Schalig | Installationsraum | 0 | A | 7.5 | 1213HWa0812968366 | NEW | no | no | 0 | 0 | no | 0 | no | Codetext | AllplanAttributes - Ortscode_Geschoßbezeichnung: E02; Sicherheitsklasse: -
 | H2 Ebene +2 | WI-LB | 1213Wa 0813194253 | yes | Codetext | m² | Trockenbauarbeiten | Wand | Innenwand 1-Schalig | WI-LB | 0 | A | 7.5 | 1213HWa0812968366 | NEW | no | no | REI 60-A1 - D,s2-d0 /A1 | 0 | no | 47 | no | Codetext | AllplanAttributes - Ortscode_Geschoßbezeichnung: E02; ash_W_Trockenbau_Qualitäten: 8; Sicherheitsklasse: -
 | H2 Ebene +2 | WI-LB | 1213Wa 0813063182 | yes | Codetext | m² | Trockenbauarbeiten | Wand | Innenwand 1-Schalig | WI-LB | 0 | A | 7.5 | 1213HWa0813063173 | NEW |  | no | 0 | 0 | no | 47 | no | Codetext | AllplanAttributes - Ortscode_Geschoßbezeichnung: E02; ash_W_Trockenbau_Qualitäten: 6; Sicherheitsklasse: -
 | H2 Ebene +2 | WI-HW 60 | 1213Wa 0813088265 | yes | Codetext | m² | Zimmer- und Holzbauarbeiten | Wand | Innenwand 1-Schalig | WI-HW 60 | 0 | A | 7.5 | 1213HWa0813063173 | NEW |  | no | 0 | 0 | no | 47 | no | Codetext | AllplanAttributes - Ortscode_Geschoßbezeichnung: E02; Sicherheitsklasse: -; ash W_laufende Nr. Statik: 3 (W 3.0)
 | H2 Ebene +2 | WI-LB | 1213Wa 0812986135 | yes | Codetext | m² | Trockenbauarbeiten | Wand | Innenwand 1-Schalig | WI-LB | 0 | A | 7.5 | 1213HWa0812968170 | NEW | no | no | 0 | 0 | no | 52 | no | Codetext | AllplanAttributes - Ortscode_Geschoßbezeichnung: E02; ash_W_Trockenbau_Qualitäten: 8; Sicherheitsklasse: -
 | H2 Ebene +2 | Installationsraum | 1213Wa 0813084864 | yes | Codetext | m² | Trockenbauarbeiten | Wand | Innenwand 1-Schalig | Installationsraum | 0 | A | 7.5 | 1213HWa0812968170 | NEW | no | no | 0 | 0 | no | 0 | no | Codetext | AllplanAttributes - Ortscode_Geschoßbezeichnung: E02; Sicherheitsklasse: -
 | H2 Ebene +2 | WI-HW 60 | 1213Wa 0813097151 | yes | Codetext | m² | Zimmer- und Holzbauarbeiten | Wand | Innenwand 1-Schalig | WI-HW 60 | 0 | A | 7.5 | 1213HWa0812968170 | NEW | no | no | 0 | 0 | no | 52 | no | Codetext | AllplanAttributes - Ortscode_Geschoßbezeichnung: E02; Sicherheitsklasse: -; ash W_laufende Nr. Statik: 3 (W 3.0)
 | H2 Ebene +2 | WI-LB | 1213Wa 0813077731 | yes | Codetext | m² | Trockenbauarbeiten | Wand | Innenwand 1-Schalig | WI-LB | 0 | A | 7.5 | 1213HWa0813077722 | NEW | no | no | 0 | 0 | no | 47 | no | Codetext | AllplanAttributes - Ortscode_Geschoßbezeichnung: E02; ash_W_Trockenbau_Qualitäten: 6; Sicherheitsklasse: -
 | H2 Ebene +2 | WI-HW 60 | 1213Wa 0813085021 | yes | Codetext | m² | Zimmer- und Holzbauarbeiten | Wand | Innenwand 1-Schalig | WI-HW 60 | 0 | A | 7.5 | 1213HWa0813077722 | NEW | no | no | 0 | 0 | no | 47 | no | Codetext | AllplanAttributes - Ortscode_Geschoßbezeichnung: E02; Sicherheitsklasse: -; ash W_laufende Nr. Statik: 3 (W 3.0)
 | H2 Ebene +2 | WI-LB | 1213Wa 0812970502 | yes | Codetext | m² | Trockenbauarbeiten | Wand | Innenwand 1-Schalig | WI-LB | 0 | A | 7.5 | 1213HWa0812968166 | NEW | no | no | 0 | 0 | no | 47 | no | Codetext | AllplanAttributes - Ortscode_Geschoßbezeichnung: E02; ash_W_Trockenbau_Qualitäten: 8; Sicherheitsklasse: -
 | H2 Ebene +2 | Installationsraum | 1213Wa 0813083917 | yes | Codetext | m² | Trockenbauarbeiten | Wand | Innenwand 1-Schalig | Installationsraum | 0 | A | 7.5 | 1213HWa0812968166 | NEW | no | no | 0 | 0 | no | 0 | no | Codetext | AllplanAttributes - Ortscode_Geschoßbezeichnung: E02; Sicherheitsklasse: -
 | H2 Ebene +2 | WI-HW 60 | 1213Wa 0813194180 | yes | Codetext | m² | Zimmer- und Holzbauarbeiten | Wand | Innenwand 1-Schalig | WI-HW 60 | 0 | A | 7.5 | 1213HWa0812968166 | NEW | no | no | 0 | 0 | no | 47 | no | Codetext | AllplanAttributes - Ortscode_Geschoßbezeichnung: E02; Sicherheitsklasse: -; ash W_laufende Nr. Statik: 3 (W 3.0)
 | H2 Ebene +2 | WI-LB | 1213Wa 0813379076 | yes | Codetext | m² | Trockenbauarbeiten | Wand | Innenwand 1-Schalig | WI-LB | 0 | A | 7.5 | 1213HWa0812968338 | NEW | no | no | 0 | 0 | no | 47 | no | Codetext | AllplanAttributes - Ortscode_Geschoßbezeichnung: E02; ash_W_Trockenbau_Qualitäten: 6; Sicherheitsklasse: -
 | H2 Ebene +2 | WI-HW 60 | 1213Wa 0813379074 | yes | Codetext | m² | Zimmer- und Holzbauarbeiten | Wand | Innenwand 1-Schalig | WI-HW 60 | 0 | A | 7.5 | 1213HWa0812968338 | NEW | no | no | 0 | 0 | no | 47 | no | Codetext | AllplanAttributes - Ortscode_Geschoßbezeichnung: E02; Sicherheitsklasse: -; ash W_laufende Nr. Statik: 3 (W 3.0)
 | H2 Ebene +2 | WI-LB | 1213Wa 0813391830 | yes | Codetext | m² | Trockenbauarbeiten | Wand | Innenwand 1-Schalig | WI-LB | 0 | A | 7.5 | 1213HWa0812968188 | NEW | no | no | 0 | 0 | no | 47 | no | Codetext | AllplanAttributes - Ortscode_Geschoßbezeichnung: E02; ash_W_Trockenbau_Qualitäten: 6; Sicherheitsklasse: -
 | H2 Ebene +2 | WI-HW 60 | 1213Wa 0813391833 | yes | Codetext | m² | Zimmer- und Holzbauarbeiten | Wand | Innenwand 1-Schalig | WI-HW 60 | 0 | A | 7.5 | 1213HWa0812968188 | NEW | no | no | 0 | 0 | no | 47 | no | Codetext | AllplanAttributes - Ortscode_Geschoßbezeichnung: E02; Sicherheitsklasse: -; ash W_laufende Nr. Statik: 3 (W 3.0)
 | H2 Ebene +2 | WI-LB | 1213Wa 0812986357 | yes | Codetext | m² | Trockenbauarbeiten | Wand | Innenwand 1-Schalig | WI-LB | 0 | A | 7.5 | 1213HWa0812968116 | NEW | no | no | 0 | 0 | no | 47 | no | Codetext | AllplanAttributes - Ortscode_Geschoßbezeichnung: E02; ash_W_Trockenbau_Qualitäten: 8; Sicherheitsklasse: -
 | H2 Ebene +2 | Installationsraum | 1213Wa 0813088433 | yes | Codetext | m² | Trockenbauarbeiten | Wand | Innenwand 1-Schalig | Installationsraum | 0 | A | 7.5 | 1213HWa0812968116 | NEW | no | no | 0 | 0 | no | 0 | no | Codetext | AllplanAttributes - Ortscode_Geschoßbezeichnung: E02; Sicherheitsklasse: -
 | H2 Ebene +2 | WI-HW 60 | 1213Wa 0813098330 | yes | Codetext | m² | Zimmer- und Holzbauarbeiten | Wand | Innenwand 1-Schalig | WI-HW 60 | 0 | A | 7.5 | 1213HWa0812968116 | NEW | no | no | 0 | 0 | no | 47 | no | Codetext | AllplanAttributes - Ortscode_Geschoßbezeichnung: E02; Sicherheitsklasse: -; ash W_laufende Nr. Statik: 3 (W 3.0)
 | H2 Ebene +2 | WI-LB | 1213Wa 0812986353 | yes | Codetext | m² | Trockenbauarbeiten | Wand | Innenwand 1-Schalig | WI-LB | 0 | A | 7.5 | 1213HWa0812968145 | NEW | no | no | 0 | 0 | no | 52 | no | Codetext | AllplanAttributes - Ortscode_Geschoßbezeichnung: E02; ash_W_Trockenbau_Qualitäten: 8; Sicherheitsklasse: -
 | H2 Ebene +2 | Installationsraum | 1213Wa 0813088012 | yes | Codetext | m² | Trockenbauarbeiten | Wand | Innenwand 1-Schalig | Installationsraum | 0 | A | 7.5 | 1213HWa0812968145 | NEW | no | no | 0 | 0 | no | 0 | no | Codetext | AllplanAttributes - Ortscode_Geschoßbezeichnung: E02; Sicherheitsklasse: -
 | H2 Ebene +2 | WI-HW 60 | 1213Wa 0813099623 | yes | Codetext | m² | Zimmer- und Holzbauarbeiten | Wand | Innenwand 1-Schalig | WI-HW 60 | 0 | A | 7.5 | 1213HWa0812968145 | NEW | no | no | 0 | 0 | no | 52 | no | Codetext | AllplanAttributes - Ortscode_Geschoßbezeichnung: E02; Sicherheitsklasse: -; ash W_laufende Nr. Statik: 3 (W 3.0)
 | H2 Ebene +2 | WI-LB | 1213Wa 0813294590 | yes | Codetext | m² | Trockenbauarbeiten | Wand | Innenwand 1-Schalig | WI-LB | 0 | A | 7.5 | 1213HWa0812968132 | NEW | no | no | 0 | 0 | no | 47 | no | Codetext | AllplanAttributes - Ortscode_Geschoßbezeichnung: E02; ash_W_Trockenbau_Qualitäten: 8; Sicherheitsklasse: -
 | H2 Ebene +2 | Installationsraum | 1213Wa 0813294587 | yes | Codetext | m² | Trockenbauarbeiten | Wand | Innenwand 1-Schalig | Installationsraum | 0 | A | 7.5 | 1213HWa0812968132 | NEW | no | no | 0 | 0 | no | 0 | no | Codetext | AllplanAttributes - Ortscode_Geschoßbezeichnung: E02; Sicherheitsklasse: -
 | H2 Ebene +2 | WI-HW 60 | 1213Wa 0813294588 | yes | Codetext | m² | Zimmer- und Holzbauarbeiten | Wand | Innenwand 1-Schalig | WI-HW 60 | 0 | A | 7.5 | 1213HWa0812968132 | NEW | no | no | 0 | 0 | no | 47 | no | Codetext | AllplanAttributes - Ortscode_Geschoßbezeichnung: E02; Sicherheitsklasse: -; ash W_laufende Nr. Statik: 3 (W 3.0)
 | H2 Ebene +2 | WI-HW 60 | 1213Wa 0813122385 | yes | Codetext | m² | Zimmer- und Holzbauarbeiten | Wand | Innenwand 1-Schalig | WI-HW 60 | 0 | A | 7.5 | 1213HWa0813122257 | NEW | no | no | REI 60-A1 - D,s2-d0 +A1 | 0 | no | 47 | no | Codetext | AllplanAttributes - Ortscode_Geschoßbezeichnung: E02; Sicherheitsklasse: -; ash W_laufende Nr. Statik: 3 (W 3.0)
 | H2 Ebene +2 | WI-LB | 1213Wa 0813122383 | yes | Codetext | m² | Trockenbauarbeiten | Wand | Innenwand 1-Schalig | WI-LB | 0 | A | 7.5 | 1213HWa0813122257 | NEW | no | no | REI 60-A1 - D,s2-d0 /A1 | 0 | no | 47 | no | Codetext | AllplanAttributes - Ortscode_Geschoßbezeichnung: E02; ash_W_Trockenbau_Qualitäten: 6; Sicherheitsklasse: -
 | H2 Ebene +2 | WI-LB | 1213Wa 0812970036 | yes | Codetext | m² | Trockenbauarbeiten | Wand | Innenwand 1-Schalig | WI-LB | 0 | A | 7.5 | 1213HWa0812968179 | NEW | no | no | 0 | 0 | no | 52 | no | Codetext | AllplanAttributes - Ortscode_Geschoßbezeichnung: E02; ash_W_Trockenbau_Qualitäten: 7; Sicherheitsklasse: -
 | H2 Ebene +2 | WI-HW 60 | 1213Wa 0813083819 | yes | Codetext | m² | Zimmer- und Holzbauarbeiten | Wand | Innenwand 1-Schalig | WI-HW 60 | 0 | A | 7.5 | 1213HWa0812968179 | NEW | no | no | 0 | 0 | no | 52 | no | Codetext | AllplanAttributes - Ortscode_Geschoßbezeichnung: E02; Sicherheitsklasse: -; ash W_laufende Nr. Statik: 3 (W 3.0)
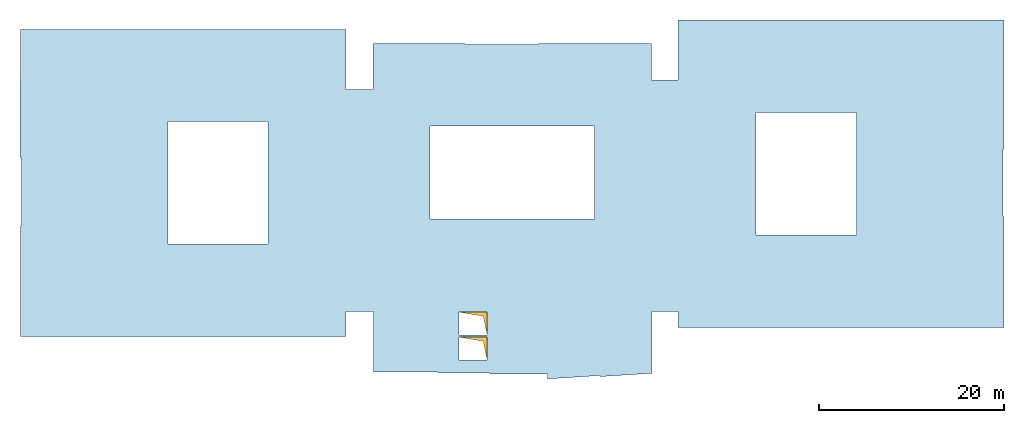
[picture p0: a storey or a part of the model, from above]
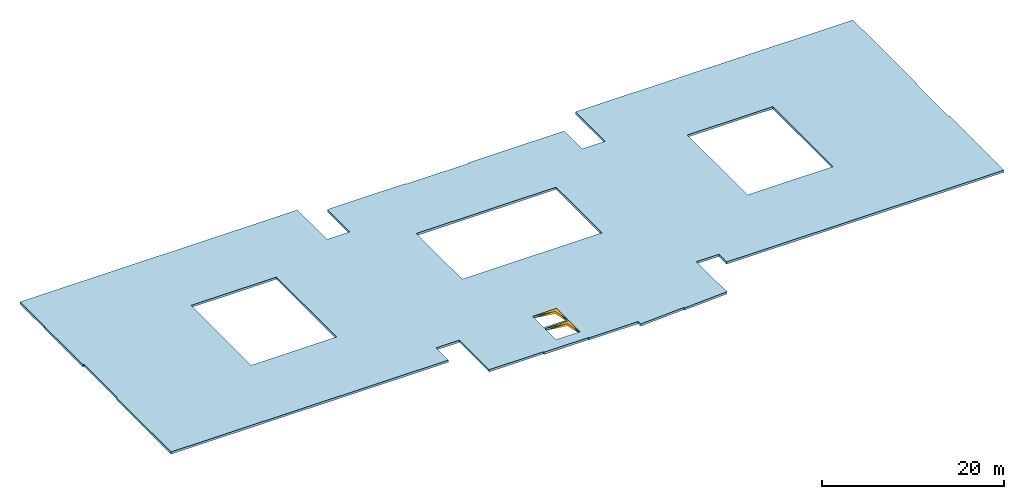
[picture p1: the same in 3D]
Properties of the parts of a building model (IFC4), part 55 of 80

# IfcWall (6826)
Name | In | Material | Allright_Bauteil_ID | 2D Interaktion | Codetext | Abrechnungsart | Gewerk | Objektname | Bezeichnung | AllplanAttributes, Material | Typ = SurfaceSpreadOfFlame | Brandschutzklasse | OKFF | P_ID | Status | LoadBearing | IsExternal | FireRating | ThermalTransmittance (W/K/m2) | Combustible | AcousticRating | Compartmentation | Reference
 | H2 Ebene +2 | WI-LB | 1213Wa 0813305853 | yes | Codetext | m² | Trockenbauarbeiten | Wand | Innenwand 1-Schalig | WI-LB | 0 | A | 7.5 | 1213HWa0812971330 | NEW | no | no | 0 | 0 | no | 52 | no | Codetext | AllplanAttributes - Ortscode_Geschoßbezeichnung: E02; ash_W_Trockenbau_Qualitäten: 8; Sicherheitsklasse: -
 | H2 Ebene +2 | Installationsraum | 1213Wa 0813305855 | yes | Codetext | m² | Trockenbauarbeiten | Wand | Innenwand 1-Schalig | Installationsraum | 0 | A | 7.5 | 1213HWa0812971330 | NEW | no | no | 0 | 0 | no | 0 | no | Codetext | AllplanAttributes - Ortscode_Geschoßbezeichnung: E02; Sicherheitsklasse: -
 | H2 Ebene +2 | WI-HW 60 | 1213Wa 0813305857 | yes | Codetext | m² | Zimmer- und Holzbauarbeiten | Wand | Innenwand 1-Schalig | WI-HW 60 | 0 | A | 7.5 | 1213HWa0812971330 | NEW | no | no | 0 | 0 | no | 52 | no | Codetext | AllplanAttributes - Ortscode_Geschoßbezeichnung: E02; Sicherheitsklasse: -; ash W_laufende Nr. Statik: 3 (W 3.0)
 | H2 Ebene +2 | WI-LB | 1213Wa 0812971276 | yes | Codetext | m² | Trockenbauarbeiten | Wand | Innenwand 1-Schalig | WI-LB | 0 | A | 7.5 | 1213HWa0812968133 | NEW | no | no | 0 | 0 | no | 47 | no | Codetext | AllplanAttributes - Ortscode_Geschoßbezeichnung: E02; ash_W_Trockenbau_Qualitäten: 8; Sicherheitsklasse: -
 | H2 Ebene +2 | Installationsraum | 1213Wa 0813088710 | yes | Codetext | m² | Trockenbauarbeiten | Wand | Innenwand 1-Schalig | Installationsraum | 0 | A | 7.5 | 1213HWa0812968133 | NEW | no | no | 0 | 0 | no | 0 | no | Codetext | AllplanAttributes - Ortscode_Geschoßbezeichnung: E02; Sicherheitsklasse: -
 | H2 Ebene +2 | WI-HW 60 | 1213Wa 0813195529 | yes | Codetext | m² | Zimmer- und Holzbauarbeiten | Wand | Innenwand 1-Schalig | WI-HW 60 | 0 | A | 7.5 | 1213HWa0812968133 | NEW | no | no | 0 | 0 | no | 47 | no | Codetext | AllplanAttributes - Ortscode_Geschoßbezeichnung: E02; Sicherheitsklasse: -; ash W_laufende Nr. Statik: 3 (W 3.0)
 | H2 Ebene +2 | WI-LB | 1213Wa 0812985917 | yes | Codetext | m² | Trockenbauarbeiten | Wand | Innenwand 1-Schalig | WI-LB | 0 | A | 7.5 | 1213HWa0812968372 | NEW | no | no | 0 | 0 | no | 52 | no | Codetext | AllplanAttributes - Ortscode_Geschoßbezeichnung: E02; ash_W_Trockenbau_Qualitäten: 6; Sicherheitsklasse: -
 | H2 Ebene +2 | WI-HW 60 | 1213Wa 0813087544 | yes | Codetext | m² | Zimmer- und Holzbauarbeiten | Wand | Innenwand 1-Schalig | WI-HW 60 | 0 | A | 7.5 | 1213HWa0812968372 | NEW | no | no | 0 | 0 | no | 52 | no | Codetext | AllplanAttributes - Ortscode_Geschoßbezeichnung: E02; Sicherheitsklasse: -; ash W_laufende Nr. Statik: 3 (W 3.0)
 | H2 Ebene +2 | WI-STB | 1213Wa 0812969944 | yes | Codetext | m² | Zimmer- und Holzbauarbeiten | Wand | Außenwand 1-Schalig | WI-STB | 0 | A | 7.5 | 1213HWa0812968502 | NEW | yes | no | REI 60-A1 - D,s2-d0 /A1 | 0 | no | 52 | no | Codetext | AllplanAttributes - Ortscode_Geschoßbezeichnung: E02
 | H2 Ebene +2 | WI-STB | 1213Wa 0812970393 | yes | Codetext | m² | Zimmer- und Holzbauarbeiten | Wand | Außenwand 1-Schalig | WI-STB | 0 | A | 7.5 | 1213HWa0812968465 | NEW | yes | no | REI 60-A1 - D,s2-d0 /A1 | 0 | no | 52 | no | Codetext | AllplanAttributes - Ortscode_Geschoßbezeichnung: E02
 | H2 Ebene +2 | WI-STB | 1213Wa 0812970361 | yes | Codetext | m² | Zimmer- und Holzbauarbeiten | Wand | Außenwand 1-Schalig | WI-STB | 0 | A | 7.5 | 1213HWa0812968108 | NEW | yes | no | REI 60-A1 - D,s2-d0 /A1 | 0 | no | 52 | no | Codetext | AllplanAttributes - Ortscode_Geschoßbezeichnung: E02
 | H2 Ebene +2 | WI-LB | 1213Wa 0812985992 |  | Codetext | m² | Trockenbauarbeiten | Wand | Innenwand 1-Schalig | WI-LB | 0 | A | 7.5 | 1213HWa0812968206 | NEW | no | no | REI 60-A1 - D,s2-d0 /A1 | 0 | no | 0 | no | Codetext | AllplanAttributes - Ortscode_Geschoßbezeichnung: E02; W_Deckenanschluss: Gleitender Deckenanschluss Fall 01; ash_W_Trockenbau_Qualitäten: 1b
 | H2 Ebene +2 | WI-STB | 1213Wa 0812970193 | yes | Codetext | m² | Zimmer- und Holzbauarbeiten | Wand | Innenwand 1-Schalig | WI-STB | 0 | A | 7.5 | 1213HWa0812968447 | NEW | yes | no | REI-M 60-A1 | 0 | no | 0 | no | Codetext | AllplanAttributes - Ortscode_Geschoßbezeichnung: E02
 | H2 Ebene +2 | WI-LB | 1213Wa 0812970190 | yes | Codetext | m² | Trockenbauarbeiten | Wand | Innenwand 1-Schalig | WI-LB | 0 | A | 7.5 | 1213HWa0812968447 | NEW | no | no | REI 60-A1 - D,s2-d0 /A1 | 0 | no | 0 | no | Codetext | AllplanAttributes - Ortscode_Geschoßbezeichnung: E02; ash_W_Trockenbau_Qualitäten: 9
 | H2 Ebene +2 | WI-LB | 1213Wa 0812985959 | yes | Codetext | m² | Trockenbauarbeiten | Wand | Außenwand 1-Schalig | WI-LB | 0 | A | 7.5 | 1213HWa0812968050 | NEW | no | no | REI 60-A1 - D,s2-d0 /A1 | 0 | no | 0 | no | Codetext | AllplanAttributes - Ortscode_Geschoßbezeichnung: E02; W_Deckenanschluss: Gleitender Deckenanschluss Fall 01; ash_W_Trockenbau_Qualitäten: 1b
 | H2 Ebene +2 | WI-STB | 1213Wa 0812985987 | yes | Codetext | m² | Zimmer- und Holzbauarbeiten | Wand | Außenwand 1-Schalig | WI-STB | 0 | A | 7.5 | 1213HWa0812968546 | NEW | yes | no | REI-M 60-A1 | 0 | no | 0 | no | Codetext | AllplanAttributes - Ortscode_Geschoßbezeichnung: E02
 | H2 Ebene +2 | WI-LB | 1213Wa 0812970205 | yes | Codetext | m² | Trockenbauarbeiten | Wand | Außenwand 1-Schalig | WI-LB | 0 | A | 7.5 | 1213HWa0812968546 | NEW | no | no | REI 60-A1 - D,s2-d0 /A1 | 0 | no | 0 | no | Codetext | AllplanAttributes - Ortscode_Geschoßbezeichnung: E02; ash_W_Trockenbau_Qualitäten: 9
 | H2 Ebene +2 | WI-LB | 1213Wa 0812986443 | yes | Codetext | m² | Trockenbauarbeiten | Wand | Innenwand 1-Schalig | WI-LB | 0 | A | 7.5 | 1213HWa0812971325 | NEW | no | no | 0 | 0 | no | 47 | no | Codetext | AllplanAttributes - Ortscode_Geschoßbezeichnung: E02; W_Deckenanschluss: Gleitender Deckenanschluss Fall 03; ash_W_Trockenbau_Qualitäten: 1b
 | H2 Ebene +2 | WI-STB | 1213Wa 0812981975 | yes | Codetext | m² | Zimmer- und Holzbauarbeiten | Wand | Innenwand 1-Schalig | WI-STB | 0 | A | 7.5 | 1213HWa0812971316 | NEW | yes | no | REI-M 60-A1 | 0 | no | 0 | no | Codetext | AllplanAttributes - Ortscode_Geschoßbezeichnung: E02
 | H2 Ebene +2 | WI-STB | 1213Wa 0812969954 | yes | Codetext | m² | Zimmer- und Holzbauarbeiten | Wand | Außenwand 1-Schalig | WI-STB | 0 | A | 7.5 | 1213HWa0812968518 | NEW | yes | no | REI-M 60-A1 | 0 | no | 0 | no | Codetext | AllplanAttributes - Ortscode_Geschoßbezeichnung: E02; Text1: Feinputz an Wandseite zum Speisewagenraum
 | H2 Ebene +2 | WI-HW 60 | 1213Wa 0812970314 | yes | Codetext | m² | Zimmer- und Holzbauarbeiten | Wand | Innenwand 1-Schalig | WI-HW 60 | 0 | A | 7.5 | 1213HWa0812968172 | NEW | yes | no | REI 30-A1 - D,s2-d0 +A1 | 0 | no | 0 | no | Codetext | AllplanAttributes - Ortscode_Geschoßbezeichnung: E02; ash W_laufende Nr. Statik: 1 (W 1.0/ 1.1/ 1.2)
 | H2 Ebene +2 | WI-HW 60 | 1213Wa 0812986361 | yes | Codetext | m² | Zimmer- und Holzbauarbeiten | Wand | Innenwand 1-Schalig | WI-HW 60 | 0 | A | 7.5 | 1213HWa0812968114 | NEW | yes | no | REI 30-A1 - D,s2-d0 +A1 | 0 | no | 0 | no | Codetext | AllplanAttributes - Ortscode_Geschoßbezeichnung: E02
 | H2 Ebene +2 | WI-LW 60 | 1213Wa 0813507831 | yes |  | m² | Trockenbauarbeiten | Wand | Innenwand 1-Schalig | WI-LW 60 |  |  | 7.5 |  | NEW | no |  | 0 | AllplanAttributes - Ortscode_Geschoßbezeichnung: E02; Sicherheitsklasse: -
 | H2 Ebene +2 | WI-LB | 1213Wa 0812970922 | yes | Codetext | m² | Trockenbauarbeiten | Wand | Innenwand 1-Schalig | WI-LB | 0 | A | 7.5 | 1213HWa0812968228 | NEW | no | no | 0 | 0 | no | 0 | no | Codetext | AllplanAttributes - Ortscode_Geschoßbezeichnung: E02; W_Deckenanschluss: Gleitender Deckenanschluss Fall 03; ash_W_Trockenbau_Qualitäten: 1b
 | H2 Ebene +2 | WI-LB | 1213Wa 0812970862 | yes | Codetext | m² | Trockenbauarbeiten | Wand | Innenwand 1-Schalig | WI-LB | 0 | A | 7.5 | 1213HWa0812968209 | NEW | no | no | 0 | 0 | no | 0 | no | Codetext | AllplanAttributes - Ortscode_Geschoßbezeichnung: E02; W_Deckenanschluss: Gleitender Deckenanschluss Fall 03; ash_W_Trockenbau_Qualitäten: 1b
 | H2 Ebene +2 | WI-LB | 1213Wa 0813019374 | yes | Codetext | m² | Trockenbauarbeiten | Wand | Innenwand 1-Schalig | WI-LB | 0 | A | 7.5 | 1213HWa0813019372 | NEW | no | no | 0 | 0 | no | 0 | no | Codetext | AllplanAttributes - Ortscode_Geschoßbezeichnung: E02; W_Deckenanschluss: Gleitender Deckenanschluss Fall 03; ash_W_Trockenbau_Qualitäten: 1b
 | H2 Ebene +2 | WI-LB | 1213Wa 0812970866 | yes | Codetext | m² | Trockenbauarbeiten | Wand | Innenwand 1-Schalig | WI-LB | 0 | A | 7.5 | 1213HWa0812968208 | NEW | no | no | 0 | 0 | no | 0 | no | Codetext | AllplanAttributes - Ortscode_Geschoßbezeichnung: E02; W_Deckenanschluss: Gleitender Deckenanschluss Fall 03; ash_W_Trockenbau_Qualitäten: 1b
 | H2 Ebene +2 | WI-LB | 1213Wa 0812970868 | yes | Codetext | m² | Trockenbauarbeiten | Wand | Innenwand 1-Schalig | WI-LB | 0 | A | 7.5 | 1213HWa0812968230 | NEW | no | no | 0 | 0 | no | 0 | no | Codetext | AllplanAttributes - Ortscode_Geschoßbezeichnung: E02; W_Deckenanschluss: Gleitender Deckenanschluss Fall 03; ash_W_Trockenbau_Qualitäten: 1b
 | H2 Ebene +2 | WI-LB | 1213Wa 0812970311 | yes | Codetext | m² | Trockenbauarbeiten | Wand | Innenwand 1-Schalig | WI-LB | 0 | A | 7.5 | 1213HWa0812968231 | NEW | no | no | 0 | 0 | no | 0 | no | Codetext | AllplanAttributes - Ortscode_Geschoßbezeichnung: E02; W_Deckenanschluss: Gleitender Deckenanschluss Fall 03; ash_W_Trockenbau_Qualitäten: 1b
 | H2 Ebene +2 | WI-LB | 1213Wa 0812970663 | yes | Codetext | m² | Trockenbauarbeiten | Wand | Innenwand 1-Schalig | WI-LB | 0 | A | 7.5 | 1213HWa0812968362 | NEW | no | no | 0 | 0 | no | 0 | no | Codetext | AllplanAttributes - Ortscode_Geschoßbezeichnung: E02; W_Deckenanschluss: Gleitender Deckenanschluss Fall 03; ash_W_Trockenbau_Qualitäten: 1b
 | H2 Ebene +2 | WI-LB | 1213Wa 0812970665 | yes | Codetext | m² | Trockenbauarbeiten | Wand | Innenwand 1-Schalig | WI-LB | 0 | A | 7.5 | 1213HWa0812968359 | NEW | no | no | 0 | 0 | no | 0 | no | Codetext | AllplanAttributes - Ortscode_Geschoßbezeichnung: E02; W_Deckenanschluss: Gleitender Deckenanschluss Fall 03; ash_W_Trockenbau_Qualitäten: 1b
 | H2 Ebene +2 | WI-LB | 1213Wa 0812970667 | yes | Codetext | m² | Trockenbauarbeiten | Wand | Innenwand 1-Schalig | WI-LB | 0 | A | 7.5 | 1213HWa0812968358 | NEW | no | no | 0 | 0 | no | 0 | no | Codetext | AllplanAttributes - Ortscode_Geschoßbezeichnung: E02; W_Deckenanschluss: Gleitender Deckenanschluss Fall 03; ash_W_Trockenbau_Qualitäten: 1b
 | H2 Ebene +2 | WI-LB | 1213Wa 0813019364 | yes | Codetext | m² | Trockenbauarbeiten | Wand | Innenwand 1-Schalig | WI-LB | 0 | A | 7.5 | 1213HWa0813019362 | NEW | no | no | 0 | 0 | no | 0 | no | Codetext | AllplanAttributes - Ortscode_Geschoßbezeichnung: E02; W_Deckenanschluss: Gleitender Deckenanschluss Fall 03; ash_W_Trockenbau_Qualitäten: 1b
 | H2 Ebene +2 | WI-LB | 1213Wa 0812982004 | yes | Codetext | m² | Trockenbauarbeiten | Wand | Innenwand 1-Schalig | WI-LB | 0 | A | 7.5 | 1213HWa0812971321 | NEW | no | no | 0 | 0 | no | 0 | no | Codetext | AllplanAttributes - Ortscode_Geschoßbezeichnung: E02; W_Deckenanschluss: Gleitender Deckenanschluss Fall 03; ash_W_Trockenbau_Qualitäten: 1b
 | H2 Ebene +2 | WI-LB | 1213Wa 0812970711 | yes | Codetext | m² | Trockenbauarbeiten | Wand | Innenwand 1-Schalig | WI-LB | 0 | A | 7.5 | 1213HWa0812968363 | NEW | no | no | 0 | 0 | no | 0 | no | Codetext | AllplanAttributes - Ortscode_Geschoßbezeichnung: E02; W_Deckenanschluss: Gleitender Deckenanschluss Fall 03; ash_W_Trockenbau_Qualitäten: 1b
 | H2 Ebene +2 | WI-GKF | 1213Wa 0812970120 | yes | Codetext | m² | Trockenbauarbeiten | Wand | "BS-Beplankung; 2-fach Gipsfaserplatten" | WI-GKF | 0 | A | 7.5 | 1213HWa0812969678 | NEW | no | no | EI 60-A1 - D,s2,d0 +A1 | 0 | no | 0 | no | Codetext | AllplanAttributes - Ortscode_Geschoßbezeichnung: E02
 | H2 Ebene +2 | WI-HW 60 | 1213Wa 0813461839 | yes |  | m² | Zimmer- und Holzbauarbeiten | Wand | Innenwand 1-Schalig | WI-HW 60 |  |  | 7.5 | 1213HWa0812968115 | NEW | no | no | REI-M 60-D,s2,d0 + A1 | AllplanAttributes - Ortscode_Geschoßbezeichnung: E02; ash W_laufende Nr. Statik: 7 (W 6.0-1)
 | H2 Ebene +2 | WI-GKF | 1213Wa 0813116566 | yes | Codetext | m² | Trockenbauarbeiten | Wand | "BS-Beplankung; 2-fach Gipsfaserplatten" | WI-GKF | 0 | A | 7.5 | 1213HWa0813116563 | NEW | no | no | EI 60-A1 - D,s2,d0 +A1 | 0 | no | 0 | no | Codetext | AllplanAttributes - Ortscode_Geschoßbezeichnung: E02
 | H2 Ebene +2 | WI-GKF | 1213Wa 0813102299 | yes | Codetext | m² | Trockenbauarbeiten | Wand | "BS-Beplankung; 2-fach Gipsfaserplatten" | WI-GKF | 0 | A | 7.5 | 1213HWa0813102297 | NEW | no | no | EI 60-A1 - D,s2,d0 +A1 | 0 | no | 0 | no | Codetext | AllplanAttributes - Ortscode_Geschoßbezeichnung: E02
 | H2 Ebene +2 | WI-GKF | 1213Wa 0812970047 | yes | Codetext | m² | Trockenbauarbeiten | Wand | "BS-Beplankung; 2-fach Gipsfaserplatten" | WI-GKF | 0 | A | 7.5 | 1213HWa0812969747 | NEW | no | no | EI 60-A1 - D,s2,d0 +A1 | 0 | no | 0 | no | Codetext | AllplanAttributes - Ortscode_Geschoßbezeichnung: E02
 | H2 Ebene +2 | WI-GKF | 1213Wa 0813102315 | yes | Codetext | m² | Trockenbauarbeiten | Wand | "BS-Beplankung; 2-fach Gipsfaserplatten" | WI-GKF | 0 | A | 7.5 | 1213HWa0813102313 | NEW | no | no | EI 60-A1 - D,s2,d0 +A1 | 0 | no | 0 | no | Codetext | AllplanAttributes - Ortscode_Geschoßbezeichnung: E02
 | H2 Ebene +2 | WI-GKF | 1213Wa 0813102308 | yes | Codetext | m² | Trockenbauarbeiten | Wand | "BS-Beplankung; 2-fach Gipsfaserplatten" | WI-GKF | 0 | A | 7.5 | 1213HWa0813102306 | NEW | no | no | EI 60-A1 - D,s2,d0 +A1 | 0 | no | 0 | no | Codetext | AllplanAttributes - Ortscode_Geschoßbezeichnung: E02
 | H2 Ebene +2 | WI-GKF | 1213Wa 0812970065 | yes | Codetext | m² | Trockenbauarbeiten | Wand | "BS-Beplankung; 2-fach Gipsfaserplatten" | WI-GKF | 0 | A | 7.5 | 1213HWa0812968376 | NEW | no | no | EI 60-A1 - D,s2,d0 +A1 | 0 | no | 0 | no | Codetext | AllplanAttributes - Ortscode_Geschoßbezeichnung: E02
 | H2 Ebene +2 | WI-GKF | 1213Wa 0812970071 | yes | Codetext | m² | Trockenbauarbeiten | Wand | "BS-Beplankung; 2-fach Gipsfaserplatten" | WI-GKF | 0 | A | 7.5 | 1213HWa0812968377 | NEW | no | no | EI 60-A1 - D,s2,d0 +A1 | 0 | no | 0 | no | Codetext | AllplanAttributes - Ortscode_Geschoßbezeichnung: E02
 | H2 Ebene +2 | WI-GKF | 1213Wa 0812970067 | yes | Codetext | m² | Trockenbauarbeiten | Wand | "BS-Beplankung; 2-fach Gipsfaserplatten" | WI-GKF | 0 | A | 7.5 | 1213HWa0812969734 | NEW | no | no | EI 60-A1 - D,s2,d0 +A1 | 0 | no | 0 | no | Codetext | AllplanAttributes - Ortscode_Geschoßbezeichnung: E02
 | H2 Ebene +2 | WI-GKF | 1213Wa 0813102173 | yes | Codetext | m² | Trockenbauarbeiten | Wand | "BS-Beplankung; 2-fach Gipsfaserplatten" | WI-GKF | 0 | A | 7.5 | 1213HWa0813102171 | NEW | no | no | EI 60-A1 - D,s2,d0 +A1 | 0 | no | 0 | no | Codetext | AllplanAttributes - Ortscode_Geschoßbezeichnung: E02
 | H2 Ebene +2 | WI-GKF | 1213Wa 0812970058 | yes | Codetext | m² | Trockenbauarbeiten | Wand | "BS-Beplankung; 2-fach Gipsfaserplatten" | WI-GKF | 0 | A | 7.5 | 1213HWa0812969739 | NEW | no | no | EI 60-A1 - D,s2,d0 +A1 | 0 | no | 0 | no | Codetext | AllplanAttributes - Ortscode_Geschoßbezeichnung: E02
 | H2 Ebene +2 | WI-GKF | 1213Wa 0812970061 | yes | Codetext | m² | Trockenbauarbeiten | Wand | "BS-Beplankung; 2-fach Gipsfaserplatten" | WI-GKF | 0 | A | 7.5 | 1213HWa0812968379 | NEW | no | no | EI 60-A1 - D,s2,d0 +A1 | 0 | no | 0 | no | Codetext | AllplanAttributes - Ortscode_Geschoßbezeichnung: E02
 | H2 Ebene +2 | WI-GKF | 1213Wa 0812969891 | yes | Codetext | m² | Trockenbauarbeiten | Wand | "BS-Beplankung; 2-fach Gipsfaserplatten" | WI-GKF | 0 | A | 7.5 | 1213HWa0812969670 | NEW | no | no | EI 60-A1 - D,s2,d0 +A1 | 0 | no | 0 | no | Codetext | AllplanAttributes - Ortscode_Geschoßbezeichnung: E02
 | H2 Ebene +2 | WI-GKF | 1213Wa 0812969899 | yes | Codetext | m² | Trockenbauarbeiten | Wand | "BS-Beplankung; 2-fach Gipsfaserplatten" | WI-GKF | 0 | A | 7.5 | 1213HWa0812969669 | NEW | no | no | EI 60-A1 - D,s2,d0 +A1 | 0 | no | 0 | no | Codetext | AllplanAttributes - Ortscode_Geschoßbezeichnung: E02
 | H2 Ebene +2 | WI-GKF | 1213Wa 0812969897 | yes | Codetext | m² | Trockenbauarbeiten | Wand | "BS-Beplankung; 2-fach Gipsfaserplatten" | WI-GKF | 0 | A | 7.5 | 1213HWa0812969671 | NEW | no | no | EI 60-A1 - D,s2,d0 +A1 | 0 | no | 0 | no | Codetext | AllplanAttributes - Ortscode_Geschoßbezeichnung: E02
 | H2 Ebene +2 | WI-GKF | 1213Wa 0812970132 | yes | Codetext | m² | Trockenbauarbeiten | Wand | "BS-Beplankung; 2-fach Gipsfaserplatten" | WI-GKF | 0 | A | 7.5 | 1213HWa0812969672 | NEW | no | no | EI 60-A1 - D,s2,d0 +A1 | 0 | no | 0 | no | Codetext | AllplanAttributes - Ortscode_Geschoßbezeichnung: E02
 | H2 Ebene +2 | WI-GKF | 1213Wa 0812970136 | yes | Codetext | m² | Trockenbauarbeiten | Wand | "BS-Beplankung; 2-fach Gipsfaserplatten" | WI-GKF | 0 | A | 7.5 | 1213HWa0812969673 | NEW | no | no | EI 60-A1 - D,s2,d0 +A1 | 0 | no | 0 | no | Codetext | AllplanAttributes - Ortscode_Geschoßbezeichnung: E02
 | H2 Ebene +2 | WI-GKF | 1213Wa 0812970134 | yes | Codetext | m² | Trockenbauarbeiten | Wand | "BS-Beplankung; 2-fach Gipsfaserplatten" | WI-GKF | 0 | A | 7.5 | 1213HWa0812968270 | NEW | no | no | EI 60-A1 - D,s2,d0 +A1 | 0 | no | 0 | no | Codetext | AllplanAttributes - Ortscode_Geschoßbezeichnung: E02
 | H2 Ebene +2 | WI-GKF | 1213Wa 0812970144 | yes | Codetext | m² | Trockenbauarbeiten | Wand | "BS-Beplankung; 2-fach Gipsfaserplatten" | WI-GKF | 0 | A | 7.5 | 1213HWa0812969633 | NEW | no | no | EI 60-A1 - D,s2,d0 +A1 | 0 | no | 0 | no | Codetext | AllplanAttributes - Ortscode_Geschoßbezeichnung: E02
 | H2 Ebene +2 | WI-GKF | 1213Wa 0812970138 | yes | Codetext | m² | Trockenbauarbeiten | Wand | "BS-Beplankung; 2-fach Gipsfaserplatten" | WI-GKF | 0 | A | 7.5 | 1213HWa0812969661 | NEW | no | no | EI 60-A1 - D,s2,d0 +A1 | 0 | no | 0 | no | Codetext | AllplanAttributes - Ortscode_Geschoßbezeichnung: E02
 | H2 Ebene +2 | WI-GKF | 1213Wa 0812970142 | yes | Codetext | m² | Trockenbauarbeiten | Wand | "BS-Beplankung; 2-fach Gipsfaserplatten" | WI-GKF | 0 | A | 7.5 | 1213HWa0812969634 | NEW | no | no | EI 60-A1 - D,s2,d0 +A1 | 0 | no | 0 | no | Codetext | AllplanAttributes - Ortscode_Geschoßbezeichnung: E02
 | H2 Ebene +2 | WI-GKF | 1213Wa 0812970140 | yes | Codetext | m² | Trockenbauarbeiten | Wand | "BS-Beplankung; 2-fach Gipsfaserplatten" | WI-GKF | 0 | A | 7.5 | 1213HWa0812969632 | NEW | no | no | EI 60-A1 - D,s2,d0 +A1 | 0 | no | 0 | no | Codetext | AllplanAttributes - Ortscode_Geschoßbezeichnung: E02
 | H2 Ebene +2 | WI-LB | 1213Wa 0812986111 |  | Codetext | m² | Trockenbauarbeiten | Wand |  |  | 0 | A | 7.5 | 1213HWa0812968297 | NEW | no | no | 0 | 0 | no | 0 | no | Codetext | AllplanAttributes - Ortscode_Geschoßbezeichnung: E02; W_Deckenanschluss: Gleitender Deckenanschluss Fall 03; ash_W_Trockenbau_Qualitäten: 10a
 | H2 Ebene +2 | WI-LB | 1213Wa 0812986256 |  | Codetext | m² | Trockenbauarbeiten | Wand |  |  | 0 | A | 7.5 | 1213HWa0812968298 | NEW | no | no | 0 | 0 | no | 0 | no | Codetext | AllplanAttributes - Ortscode_Geschoßbezeichnung: E02; W_Deckenanschluss: Gleitender Deckenanschluss Fall 03; ash_W_Trockenbau_Qualitäten: 10a
 | H2 Ebene +2 | WI-LB | 1213Wa 0812986244 |  | Codetext | m² | Trockenbauarbeiten | Wand |  |  | 0 | A | 7.5 | 1213HWa0812968299 | NEW | no | no | 0 | 0 | no | 0 | no | Codetext | AllplanAttributes - Ortscode_Geschoßbezeichnung: E02; W_Deckenanschluss: Gleitender Deckenanschluss Fall 03; ash_W_Trockenbau_Qualitäten: 10a
 | H2 Ebene +2 | WI-LB | 1213Wa 0812986252 |  | Codetext | m² | Trockenbauarbeiten | Wand |  |  | 0 | A | 7.5 | 1213HWa0812968300 | NEW | no | no | 0 | 0 | no | 0 | no | Codetext | AllplanAttributes - Ortscode_Geschoßbezeichnung: E02; W_Deckenanschluss: Gleitender Deckenanschluss Fall 03; ash_W_Trockenbau_Qualitäten: 10a
 | H2 Ebene +2 | WI-LB | 1213Wa 0812986248 |  | Codetext | m² | Trockenbauarbeiten | Wand |  |  | 0 | A | 7.5 | 1213HWa0812968301 | NEW | no | no | 0 | 0 | no | 0 | no | Codetext | AllplanAttributes - Ortscode_Geschoßbezeichnung: E02; W_Deckenanschluss: Gleitender Deckenanschluss Fall 03; ash_W_Trockenbau_Qualitäten: 10a
 | H2 Ebene +2 | WI-LB | 1213Wa 0812986240 |  | Codetext | m² | Trockenbauarbeiten | Wand |  |  | 0 | A | 7.5 | 1213HWa0812968302 | NEW | no | no | 0 | 0 | no | 0 | no | Codetext | AllplanAttributes - Ortscode_Geschoßbezeichnung: E02; W_Deckenanschluss: Gleitender Deckenanschluss Fall 03; ash_W_Trockenbau_Qualitäten: 10a
 | H2 Ebene +2 | WI-LB | 1213Wa 0812970709 |  | Codetext | m² | Trockenbauarbeiten | Wand |  |  | 0 | A | 7.5 | 1213HWa0812968306 | NEW | no | no | 0 | 0 | no | 0 | no | Codetext | AllplanAttributes - Ortscode_Geschoßbezeichnung: E02; W_Deckenanschluss: Gleitender Deckenanschluss Fall 03; ash_W_Trockenbau_Qualitäten: 10a
 | H2 Ebene +2 | WI-LB | 1213Wa 0812970265 |  | Codetext | m² | Trockenbauarbeiten | Wand |  |  | 0 | A | 7.5 | 1213HWa0812968307 | NEW | no | no | 0 | 0 | no | 0 | no | Codetext | AllplanAttributes - Ortscode_Geschoßbezeichnung: E02; W_Deckenanschluss: Gleitender Deckenanschluss Fall 03; ash_W_Trockenbau_Qualitäten: 10a
 | H2 Ebene +2 | WI-LB | 1213Wa 0812970267 |  | Codetext | m² | Trockenbauarbeiten | Wand |  |  | 0 | A | 7.5 | 1213HWa0812968308 | NEW | no | no | 0 | 0 | no | 0 | no | Codetext | AllplanAttributes - Ortscode_Geschoßbezeichnung: E02; W_Deckenanschluss: Gleitender Deckenanschluss Fall 03; ash_W_Trockenbau_Qualitäten: 10a
 | H2 Ebene +2 | WI-LB | 1213Wa 0812982006 | yes | Codetext | m² | Trockenbauarbeiten | Wand | Innenwand 1-Schalig | WI-LB | 0 | A | 7.5 | 1213HWa0812971320 | NEW | no | no | 0 | 0 | no | 0 | no | Codetext | AllplanAttributes - Ortscode_Geschoßbezeichnung: E02; W_Deckenanschluss: Gleitender Deckenanschluss Fall 03; ash_W_Trockenbau_Qualitäten: 1b
 | H2 Ebene +2 | WI-LB | 1213Wa 0813019328 | yes | Codetext | m² | Trockenbauarbeiten | Wand | Innenwand 1-Schalig | WI-LB | 0 | A | 7.5 | 1213HWa0813019326 | NEW | no | no | 0 | 0 | no | 0 | no | Codetext | AllplanAttributes - Ortscode_Geschoßbezeichnung: E02; W_Deckenanschluss: Gleitender Deckenanschluss Fall 03; ash_W_Trockenbau_Qualitäten: 1b
 | H2 Ebene +2 | WI-LB | 1213Wa 0812970301 | yes | Codetext | m² | Trockenbauarbeiten | Wand | Innenwand 1-Schalig | WI-LB | 0 | A | 7.5 | 1213HWa0812968317 | NEW | no | no | 0 | 0 | no | 0 | no | Codetext | AllplanAttributes - Ortscode_Geschoßbezeichnung: E02; W_Deckenanschluss: Gleitender Deckenanschluss Fall 03; ash_W_Trockenbau_Qualitäten: 1b
 | H2 Ebene +2 | WI-LB | 1213Wa 0812970559 | yes | Codetext | m² | Trockenbauarbeiten | Wand | Innenwand 1-Schalig | WI-LB | 0 | A | 7.5 | 1213HWa0812968316 | NEW | no | no | 0 | 0 | no | 0 | no | Codetext | AllplanAttributes - Ortscode_Geschoßbezeichnung: E02; W_Deckenanschluss: Gleitender Deckenanschluss Fall 03; ash_W_Trockenbau_Qualitäten: 1b
 | H2 Ebene +2 | WI-LB | 1213Wa 0812970774 | yes | Codetext | m² | Trockenbauarbeiten | Wand | Innenwand 1-Schalig | WI-LB | 0 | A | 7.5 | 1213HWa0812968320 | NEW | no | no | 0 | 0 | no | 0 | no | Codetext | AllplanAttributes - Ortscode_Geschoßbezeichnung: E02; W_Deckenanschluss: Gleitender Deckenanschluss Fall 03; ash_W_Trockenbau_Qualitäten: 1b
 | H2 Ebene +2 | WI-LB | 1213Wa 0812986152 | yes | Codetext | m² | Trockenbauarbeiten | Wand | Innenwand 1-Schalig | WI-LB | 0 | A | 7.5 | 1213HWa0812968062 | NEW | no | no | 0 | 0 | no |  | no | Codetext | AllplanAttributes - Ortscode_Geschoßbezeichnung: E02; W_Deckenanschluss: Gleitender Deckenanschluss Fall 01; ash_W_Trockenbau_Qualitäten: 4
 | H2 Ebene +2 | WI-LB | 1213Wa 0812986465 |  | Codetext | m² | Trockenbauarbeiten | Wand |  |  | 0 | A | 7.5 | 1213HWa0812968234 | NEW | no | no | 0 | 0 | no | 0 | no | Codetext | AllplanAttributes - Ortscode_Geschoßbezeichnung: E02; W_Deckenanschluss: Gleitender Deckenanschluss Fall 03; ash_W_Trockenbau_Qualitäten: 10a
 | H2 Ebene +2 | WI-LB | 1213Wa 0813563070 | yes | Codetext | m² | Trockenbauarbeiten | Wand | Innenwand 1-Schalig | WI-LB | 0 | A | 7.5 | 1213HWa0812968205 | NEW | no | no | REI 30-A1 - D,s2-d0 +A1 | 0 | no | 47 | no | Codetext | AllplanAttributes - Ortscode_Geschoßbezeichnung: E02; W_Deckenanschluss: Gleitender Deckenanschluss Fall 01; ash_W_Trockenbau_Qualitäten: 1b
 | H2 Ebene +2 | WI-LB | 1213Wa 0812970549 |  | Codetext | m² | Trockenbauarbeiten | Wand | Innenwand 1-Schalig | WI-LB | 0 | A | 7.5 | 1213HWa0812968099 | NEW |  | no | REI 60-A1 - D,s2-d0 +A1 | 0 | no | 0 | no | Codetext | AllplanAttributes - Ortscode_Geschoßbezeichnung: E02; W_Deckenanschluss: Gleitender Deckenanschluss Fall 01; ash_W_Trockenbau_Qualitäten: 1b
 | H2 Ebene +2 | WI-LB | 1213Wa 0812986349 | yes | Codetext | m² | Trockenbauarbeiten | Wand | Innenwand 1-Schalig | WI-LB | 0 | A | 7.5 | 1213HWa0812968081 | NEW | no | no | 0 | 0 | no | 0 | no | Codetext | AllplanAttributes - Ortscode_Geschoßbezeichnung: E02; W_Deckenanschluss: Gleitender Deckenanschluss Fall 01; ash_W_Trockenbau_Qualitäten: 1b
 | H2 Ebene +2 | WI-LB | 1213Wa 0812986093 | yes | Codetext | m² | Trockenbauarbeiten | Wand | Innenwand 1-Schalig | WI-LB | 0 | A | 7.5 | 1213HWa0812968339 | NEW | no | no | REI 30-A1 - D,s2-d0 +A1 | 0 | no | 47 | no | Codetext | AllplanAttributes - Ortscode_Geschoßbezeichnung: E02; W_Deckenanschluss: Gleitender Deckenanschluss Fall 01; ash_W_Trockenbau_Qualitäten: 1b
 | H2 Ebene +2 | WI-LB | 1213Wa 0813563773 | yes | Codetext | m² | Trockenbauarbeiten | Wand | Innenwand 1-Schalig | WI-LB | 0 | A | 7.5 | 1213HWa0812968059 | NEW |  | no | REI 60-A1 - D,s2-d0 +A1 | 0 | no | 0 | no | Codetext | AllplanAttributes - Ortscode_Geschoßbezeichnung: E02; W_Deckenanschluss: Gleitender Deckenanschluss Fall 01; ash_W_Trockenbau_Qualitäten: 1b
 | H2 Ebene +2 | WI-STB | 1213Wa 0813480804 | yes |  | m² | Zimmer- und Holzbauarbeiten | Wand | Innenwand 1-Schalig | WI-STB |  |  | 7.5 |  | NEW | no |  | 0 |  |  | 0 | AllplanAttributes - Ortscode_Geschoßbezeichnung: E02; Sicherheitsklasse: -
 | H2 Ebene +2 | WI-STB | 1213Wa 0813480805 | yes |  | m² | Zimmer- und Holzbauarbeiten | Wand | Innenwand 1-Schalig | WI-STB |  |  | 7.5 |  | NEW | no |  | 0 |  |  | 0 | AllplanAttributes - Ortscode_Geschoßbezeichnung: E02; Sicherheitsklasse: -
 | H2 Ebene +2 | WI-LB | 1213Wa 0813480806 | yes |  | m² | Trockenbauarbeiten | Wand | Innenwand 1-Schalig | WI-LB |  |  | 7.5 |  | NEW | no |  | 0 |  |  | 0 | AllplanAttributes - Ortscode_Geschoßbezeichnung: E02; ash_W_Trockenbau_Qualitäten: 9; Sicherheitsklasse: -
 | H2 Ebene +2 | WI-STB | 1213Wa 0812986438 | yes | Codetext | m² | Zimmer- und Holzbauarbeiten | Wand | Außenwand 1-Schalig | WI-STB | 0 | A | 7.5 | 1213HWa0812968515 | NEW | yes | no | REI 60-A1 - D,s2-d0 /A1 | 0 | no | 0 | no | Codetext | AllplanAttributes - Ortscode_Geschoßbezeichnung: E02
 | H2 Ebene +2 | WI-LB | 1213Wa 0812985921 | yes | Codetext | m² | Trockenbauarbeiten | Wand | Außenwand 1-Schalig | WI-LB | 0 | A | 7.5 | 1213HWa0812968515 | NEW | no | no | REI 60-A1 - D,s2-d0 /A1 | 0 | no | 0 | no | Codetext | AllplanAttributes - Ortscode_Geschoßbezeichnung: E02; ash_W_Trockenbau_Qualitäten: 9
 | H2 Ebene +2 | WI-STB | 1213Wa 0812981977 | yes | Codetext | m² | Zimmer- und Holzbauarbeiten | Wand | Außenwand 1-Schalig | WI-STB | 0 | A | 7.5 | 1213HWa0812971317 | NEW | yes | no | REI-M 60-A1 | 0 | no | 0 | no | Codetext | AllplanAttributes - Ortscode_Geschoßbezeichnung: E02
 | H2 Ebene +2 | WI-LB | 1213Wa 0813563464 | yes | Codetext | m² | Trockenbauarbeiten | Wand | Innenwand 1-Schalig | WI-LB | 0 | A | 7.5 | 1213HWa0812968081 | NEW | no | no | 0 | 0 | no | 0 | no | Codetext | AllplanAttributes - Ortscode_Geschoßbezeichnung: E02; ash D_Detailverweis: FL1; ash D_Plannummer: 1680; W_Deckenanschluss: Gleitender Deckenanschluss Fall 01; ash_W_Trockenbau_Qualitäten: 1a
 | H2 Ebene +2 | WI-LB | 1213Wa 0813568680 | yes | Codetext | m² | Trockenbauarbeiten | Wand | Innenwand 1-Schalig | WI-LB | 0 | A | 7.5 | 1213HWa0812968059 | NEW |  | no | REI 60-A1 - D,s2-d0 +A1 | 0 | no | 0 | no | Codetext | AllplanAttributes - Ortscode_Geschoßbezeichnung: E02; W_Deckenanschluss: Gleitender Deckenanschluss Fall 01; ash_W_Trockenbau_Qualitäten: 1a
 | H2 Ebene +2 | WI-LB | 1213Wa 0813056944 | yes | Codetext | m² | Trockenbauarbeiten | Wand | Innenwand 1-Schalig | WI-LB | 0 | A | 7.5 | 1213HWa0813056943 | NEW |  | no | 0 | 0 | no | 47 | no | Codetext | AllplanAttributes - Ortscode_Geschoßbezeichnung: E02; W_Deckenanschluss: Gleitender Deckenanschluss Fall 03; ash_W_Trockenbau_Qualitäten: 1a
 | H2 Ebene +2 | WI-LB | 1213Wa 0813568923 | yes | Codetext | m² | Trockenbauarbeiten | Wand | Innenwand 1-Schalig | WI-LB | 0 | A | 7.5 | 1213HWa0813057754 | NEW |  | no | 0 | 0 | no | 47 | no | Codetext | AllplanAttributes - Ortscode_Geschoßbezeichnung: E02; W_Deckenanschluss: Gleitender Deckenanschluss Fall 03; ash_W_Trockenbau_Qualitäten: 1a
 | H2 Ebene +2 | WI-LB | 1213Wa 0813569089 | yes | Codetext | m² | Trockenbauarbeiten | Wand | Innenwand 1-Schalig | WI-LB | 0 | A | 7.5 | 1213HWa0812968431 | NEW | no | no | REI 60-A1 - D,s2-d0 +A1 | 0 | no | 0 | no | Codetext | AllplanAttributes - Ortscode_Geschoßbezeichnung: E02; W_Deckenanschluss: Gleitender Deckenanschluss Fall 01; ash_W_Trockenbau_Qualitäten: 1b
 | H2 Ebene +2 | WI-LB | 1213Wa 0813569120 | yes | Codetext | m² | Trockenbauarbeiten | Wand | Innenwand 1-Schalig | WI-LB | 0 | A | 7.5 | 1213HWa0812968205 | NEW | no | no | REI 30-A1 - D,s2-d0 +A1 | 0 | no | 47 | no | Codetext | AllplanAttributes - Ortscode_Geschoßbezeichnung: E02; W_Deckenanschluss: Gleitender Deckenanschluss Fall 01; ash_W_Trockenbau_Qualitäten: 1a
 | H2 Ebene +2 | WI-LB | 1213Wa 0813569580 | yes | Codetext | m² | Trockenbauarbeiten | Wand | Innenwand 1-Schalig | WI-LB | 0 | A | 7.5 | 1163HWa0812705301 | NEW | no | no | 0 | 0 | no | 0 | no | Codetext | AllplanAttributes - Ortscode_Geschoßbezeichnung: E02; W_Deckenanschluss: Gleitender Deckenanschluss Fall 01; Positionsnummer_Text: U100
 | H2 Ebene +2 | WI-HW 60 | 1213Wa 0812969904 | yes | Codetext | m² | Zimmer- und Holzbauarbeiten | Wand | Innenwand 1-Schalig | WI-HW 60 | 0 | A | 7.5 | 1213HWa0812969820 | NEW | no | no | REI 60-A1 - D,s2-d0 +A1 | 0 | no | 52 | no | Codetext | AllplanAttributes - Ortscode_Geschoßbezeichnung: E02; Sicherheitsklasse: -; ash W_laufende Nr. Statik: 1 (W 1.0/ 1.1/ 1.2)
 | H2 Ebene +2 | WI-LB | 1213Wa 0813088161 | yes | Codetext | m² | Trockenbauarbeiten | Wand | Innenwand 1-Schalig | WI-LB | 0 | A | 7.5 | 1213HWa0812969820 | NEW | no | no | REI 60-A1 - D,s2-d0 /A1 | 0 | no | 52 | no | Codetext | AllplanAttributes - Ortscode_Geschoßbezeichnung: E02; ash_W_Trockenbau_Qualitäten: 6; Sicherheitsklasse: -
 | H2 Ebene +2 | WI-HW 60 | 1213Wa 0813331101 | yes | Codetext | m² | Zimmer- und Holzbauarbeiten | Wand | Innenwand 1-Schalig | WI-HW 60 | 0 | A | 7.5 | 1213HWa0812968167 | NEW | no | no | REI 60-A1 - D,s2-d0 +A1 | 0 | no | 52 | no | Codetext | AllplanAttributes - Ortscode_Geschoßbezeichnung: E02; Sicherheitsklasse: -; ash W_laufende Nr. Statik: 3 (W 3.0)
 | H2 Ebene +2 | WI-LB | 1213Wa 0813331099 | yes | Codetext | m² | Trockenbauarbeiten | Wand | Innenwand 1-Schalig | WI-LB | 0 | A | 7.5 | 1213HWa0812968167 | NEW | no | no | REI 60-A1 - D,s2-d0 /A1 | 0 | no | 52 | no | Codetext | AllplanAttributes - Ortscode_Geschoßbezeichnung: E02; ash_W_Trockenbau_Qualitäten: 6; Sicherheitsklasse: -
 | H2 Ebene +2 | WI-LB | 1213Wa 0812986317 |  | Codetext | m² | Trockenbauarbeiten | Wand |  |  | 0 | A | 7.5 | 1213HWa0812968240 | NEW | no | no | 0 | 0 | no | 0 | no | Codetext | AllplanAttributes - Ortscode_Geschoßbezeichnung: E02; W_Deckenanschluss: Gleitender Deckenanschluss Fall 03; ash_W_Trockenbau_Qualitäten: 10a
 | H2 Ebene +2 | WI-LB | 1213Wa 0812986313 |  | Codetext | m² | Trockenbauarbeiten | Wand |  |  | 0 | A | 7.5 | 1213HWa0812968241 | NEW | no | no | 0 | 0 | no | 0 | no | Codetext | AllplanAttributes - Ortscode_Geschoßbezeichnung: E02; W_Deckenanschluss: Gleitender Deckenanschluss Fall 03; ash_W_Trockenbau_Qualitäten: 10a
 | H2 Ebene +2 | WI-LB | 1213Wa 0812986305 |  | Codetext | m² | Trockenbauarbeiten | Wand |  |  | 0 | A | 7.5 | 1213HWa0812968242 | NEW | no | no | 0 | 0 | no | 0 | no | Codetext | AllplanAttributes - Ortscode_Geschoßbezeichnung: E02; W_Deckenanschluss: Gleitender Deckenanschluss Fall 03; ash_W_Trockenbau_Qualitäten: 10a
 | H2 Ebene +2 | WI-LB | 1213Wa 0812986309 |  | Codetext | m² | Trockenbauarbeiten | Wand |  |  | 0 | A | 7.5 | 1213HWa0812968244 | NEW | no | no | 0 | 0 | no | 0 | no | Codetext | AllplanAttributes - Ortscode_Geschoßbezeichnung: E02; W_Deckenanschluss: Gleitender Deckenanschluss Fall 03; ash_W_Trockenbau_Qualitäten: 10a
 | H2 Ebene +2 | WI-LB | 1213Wa 0812986297 |  | Codetext | m² | Trockenbauarbeiten | Wand |  |  | 0 | A | 7.5 | 1213HWa0812968246 | NEW | no | no | 0 | 0 | no | 0 | no | Codetext | AllplanAttributes - Ortscode_Geschoßbezeichnung: E02; W_Deckenanschluss: Gleitender Deckenanschluss Fall 03; ash_W_Trockenbau_Qualitäten: 10a
 | H2 Ebene +2 | WI-LB | 1213Wa 0812986301 |  | Codetext | m² | Trockenbauarbeiten | Wand |  |  | 0 | A | 7.5 | 1213HWa0812968247 | NEW | no | no | 0 | 0 | no | 0 | no | Codetext | AllplanAttributes - Ortscode_Geschoßbezeichnung: E02; W_Deckenanschluss: Gleitender Deckenanschluss Fall 03; ash_W_Trockenbau_Qualitäten: 10a
 | H2 Ebene +2 | WI-LB | 1213Wa 0812986293 |  | Codetext | m² | Trockenbauarbeiten | Wand |  |  | 0 | A | 7.5 | 1213HWa0812968259 | NEW | no | no | 0 | 0 | no | 0 | no | Codetext | AllplanAttributes - Ortscode_Geschoßbezeichnung: E02; W_Deckenanschluss: Gleitender Deckenanschluss Fall 03; ash_W_Trockenbau_Qualitäten: 10a
 | H2 Ebene +2 | WI-LB | 1213Wa 0812970629 |  | Codetext | m² | Trockenbauarbeiten | Wand | Innenwand 1-Schalig | WI-LB | 0 | A | 7.5 | 1213HWa0812968422 | NEW |  | no | REI 30 | 0 | no | 47 | no | Codetext | AllplanAttributes - Ortscode_Geschoßbezeichnung: E02; W_Deckenanschluss: Gleitender Deckenanschluss Fall 03; ash_W_Trockenbau_Qualitäten: 1c
 | H2 Ebene +2 | WI-LB | 1213Wa 0812970626 |  | Codetext | m² | Trockenbauarbeiten | Wand |  |  | 0 | A | 7.5 | 1213HWa0812968044 | NEW |  | no | 0 | 0 | no | 47 | no | Codetext | AllplanAttributes - Ortscode_Geschoßbezeichnung: E02; W_Deckenanschluss: Gleitender Deckenanschluss Fall 03; ash_W_Trockenbau_Qualitäten: 1c
 | H2 Ebene +2 | WI-LB | 1213Wa 0812970634 |  | Codetext | m² | Trockenbauarbeiten | Wand | Innenwand 1-Schalig | WI-LB | 0 | A | 7.5 | 1213HWa0812968421 | NEW |  | no | REI 30 | 0 | no | 47 | no | Codetext | AllplanAttributes - Ortscode_Geschoßbezeichnung: E02; W_Deckenanschluss: Gleitender Deckenanschluss Fall 03; ash_W_Trockenbau_Qualitäten: 1c
 | H2 Ebene +2 | WI-LB | 1213Wa 0812970621 |  | Codetext | m² | Trockenbauarbeiten | Wand |  |  | 0 | A | 7.5 | 1213HWa0812968045 | NEW |  | no | 0 | 0 | no | 47 | no | Codetext | AllplanAttributes - Ortscode_Geschoßbezeichnung: E02; W_Deckenanschluss: Gleitender Deckenanschluss Fall 03; ash_W_Trockenbau_Qualitäten: 1c
 | H2 Ebene +2 | WI-LB | 1213Wa 0812970972 |  | Codetext | m² | Trockenbauarbeiten | Wand | Innenwand 1-Schalig | WI-LB | 0 | A | 7.5 | 1213HWa0812968420 | NEW |  | no | REI 30 | 0 | no | 47 | no | Codetext | AllplanAttributes - Ortscode_Geschoßbezeichnung: E02; W_Deckenanschluss: Gleitender Deckenanschluss Fall 03; ash_W_Trockenbau_Qualitäten: 1c
 | H2 Ebene +2 | WI-LB | 1213Wa 0813054770 | yes | Codetext | m² | Trockenbauarbeiten | Wand | Innenwand 1-Schalig | WI-LB | 0 | A | 7.5 | 1213HWa0813054768 | NEW | no | no | 0 | 0 | no | 0 | no | Codetext | AllplanAttributes - Ortscode_Geschoßbezeichnung: E02; ash_W_Trockenbau_Qualitäten: 8
 | H2 Ebene +2 | WI-LB | 1213Wa 0813054741 | yes | Codetext | m² | Trockenbauarbeiten | Wand | Innenwand 1-Schalig | WI-LB | 0 | A | 7.5 | 1213HWa0813054739 | NEW | no | no | 0 | 0 | no | 0 | no | Codetext | AllplanAttributes - Ortscode_Geschoßbezeichnung: E02; ash_W_Trockenbau_Qualitäten: 8
 | H2 Ebene +2 | WI-LB | 1213Wa 0813054733 | yes | Codetext | m² | Trockenbauarbeiten | Wand | Innenwand 1-Schalig | WI-LB | 0 | A | 7.5 | 1213HWa0813054731 | NEW | no | no | 0 | 0 | no | 0 | no | Codetext | AllplanAttributes - Ortscode_Geschoßbezeichnung: E02; ash_W_Trockenbau_Qualitäten: 8
 | H2 Ebene +2 | WI-LW 60 | 1213Wa 0813186186 | yes |  | m² | Trockenbauarbeiten | Wand | Innenwand 1-Schalig | WI-LW 60 |  |  | 7.5 | 1213HWa0813186069 | NEW | no | no | REI-M 60-D,s2,d0 + A1 |  |  | 47 | AllplanAttributes - Ortscode_Geschoßbezeichnung: E02; ash_W_Trockenbau_Qualitäten: 12a
 | H2 Ebene +2 | Installationsraum | 1213Wa 0812971263 | yes | Codetext | m² | Trockenbauarbeiten | Wand | Installationswand | Installationsraum | 0 | A | 7.5 | 1213HWa0812968055 | NEW | no | no | 0 | 0 | no | 0 | no | Codetext | AllplanAttributes - Ortscode_Geschoßbezeichnung: E02
 | H2 Ebene +2 | WI-VS | 1213Wa 0812971261 | yes | Codetext | m² | Trockenbauarbeiten | Wand | Installationswand | WI-VS | 0 | A | 7.5 | 1213HWa0812968055 | NEW | no | no | 0 | 0 | no | 0 | no | Codetext | AllplanAttributes - Ortscode_Geschoßbezeichnung: E02; W_Deckenanschluss: Gleitender Deckenanschluss Fall 01; ash_W_Trockenbau_Qualitäten: 2
 | H2 Ebene +2 | WI-LB | 1213Wa 0813055506 | yes | Codetext | m² | Trockenbauarbeiten | Wand | Innenwand 1-Schalig | WI-LB | 0 | A | 7.5 | 1213HWa0813055490 | NEW | no | no | 0 | 0 | no | 0 | no | Codetext | AllplanAttributes - Ortscode_Geschoßbezeichnung: E02; ash_W_Trockenbau_Qualitäten: 16
 | H2 Ebene +2 | WI-IW | 1213Wa 0813062160 | yes | Codetext | m² | Trockenbauarbeiten | Wand | Installationswand | WI-IW | 0 | A | 7.5 | 1213HWa0813062159 | NEW | no | no | 0 | 0 | no | 0 | no | Codetext | AllplanAttributes - Ortscode_Geschoßbezeichnung: E02; ash_W_Trockenbau_Qualitäten: 8
 | H2 Ebene +2 | Installationsraum | 1213Wa 0812970557 | yes | Codetext | m² | Trockenbauarbeiten | Wand | Installationswand | Installationsraum | 0 | A | 7.5 | 1213HWa0812968148 | NEW | no | no | 0 | 0 | no | 0 | no | Codetext | AllplanAttributes - Ortscode_Geschoßbezeichnung: E02
 | H2 Ebene +2 | WI-VS | 1213Wa 0812971259 | yes | Codetext | m² | Trockenbauarbeiten | Wand | Installationswand | WI-VS | 0 | A | 7.5 | 1213HWa0812968148 | NEW | no | no | 0 | 0 | no | 0 | no | Codetext | AllplanAttributes - Ortscode_Geschoßbezeichnung: E02; W_Deckenanschluss: Gleitender Deckenanschluss Fall 01; ash_W_Trockenbau_Qualitäten: 2
 | H2 Ebene +2 | WI-IW | 1213Wa 0812981998 | yes | Codetext | m² | Trockenbauarbeiten | Wand | Installationswand | WI-IW | 0 | A | 7.5 | 1213HWa0812971329 | NEW | no | no | 0 | 0 | no | 0 | no | Codetext | AllplanAttributes - Ortscode_Geschoßbezeichnung: E02; W_Deckenanschluss: Gleitender Deckenanschluss Fall 01; ash_W_Trockenbau_Qualitäten: 11
 | H2 Ebene +2 | Installationsraum | 1213Wa 0812982000 | yes | Codetext | m² | Trockenbauarbeiten | Wand | Installationswand | Installationsraum | 0 | A | 7.5 | 1213HWa0812971329 | NEW | no | no | 0 | 0 | no | 0 | no | Codetext | AllplanAttributes - Ortscode_Geschoßbezeichnung: E02
 | H2 Ebene +2 | WI-IW | 1213Wa 0812982002 | yes | Codetext | m² | Trockenbauarbeiten | Wand | Installationswand | WI-IW | 0 | A | 7.5 | 1213HWa0812971329 | NEW | no | no | 0 | 0 | no | 0 | no | Codetext | AllplanAttributes - Ortscode_Geschoßbezeichnung: E02; W_Deckenanschluss: Gleitender Deckenanschluss Fall 01; ash_W_Trockenbau_Qualitäten: 11
 | H2 Ebene +2 | Installationsraum | 1213Wa 0812970480 | yes | Codetext | m² | Trockenbauarbeiten | Wand | Installationswand | Installationsraum | 0 | A | 7.5 | 1213HWa0812968157 | NEW | no | no | 0 | 0 | no | 0 | no | Codetext | AllplanAttributes - Ortscode_Geschoßbezeichnung: E02
 | H2 Ebene +2 | WI-VS | 1213Wa 0812970474 | yes | Codetext | m² | Trockenbauarbeiten | Wand | Installationswand | WI-VS | 0 | A | 7.5 | 1213HWa0812968157 | NEW | no | no | 0 | 0 | no | 0 | no | Codetext | AllplanAttributes - Ortscode_Geschoßbezeichnung: E02; W_Deckenanschluss: Gleitender Deckenanschluss Fall 01; ash_W_Trockenbau_Qualitäten: 5
 | H2 Ebene +2 | Installationsraum | 1213Wa 0812970470 | yes | Codetext | m² | Trockenbauarbeiten | Wand | Installationswand | Installationsraum | 0 | A | 7.5 | 1213HWa0812968281 | NEW | no | no | 0 | 0 | no | 0 | no | Codetext | AllplanAttributes - Ortscode_Geschoßbezeichnung: E02
 | H2 Ebene +2 | WI-VS | 1213Wa 0812970476 | yes | Codetext | m² | Trockenbauarbeiten | Wand | Installationswand | WI-VS | 0 | A | 7.5 | 1213HWa0812968281 | NEW | no | no | 0 | 0 | no | 0 | no | Codetext | AllplanAttributes - Ortscode_Geschoßbezeichnung: E02; W_Deckenanschluss: Gleitender Deckenanschluss Fall 01; ash_W_Trockenbau_Qualitäten: 5
 | H2 Ebene +2 | WI-IW | 1213Wa 0812971227 | yes | Codetext | m² | Trockenbauarbeiten | Wand | Innenwand 1-Schalig | WI-IW | 0 | A | 7.5 | 1163HWa0813718658 | NEW | no | no | 0 | 0 | no | 52 | no | Codetext | AllplanAttributes - Ortscode_Geschoßbezeichnung: E02; ash_W_Trockenbau_Qualitäten: 16; Positionsnummer_Text: U100
 | H2 Ebene +2 | WI-HW 60 | 1213Wa 0813507457 | yes |  | m² | Zimmer- und Holzbauarbeiten | Wand | Innenwand 1-Schalig | WI-HW 60 |  |  | 7.5 | 1213HWa0812968159 | NEW | no | no | REI-M 60-D,s2,d0 + A1 |  |  | 52 | AllplanAttributes - Ortscode_Geschoßbezeichnung: E02; ash W_laufende Nr. Statik: 7 (W 6.0-1)
 | H2 Ebene +2 | Installationsraum | 1213Wa 0812969956 | yes | Codetext | m² | Trockenbauarbeiten | Wand | Installationswand | Installationsraum | 0 | A | 7.5 | 1213HWa0812968105 | NEW | no | no | 0 | 0 | no | 0 | no | Codetext | AllplanAttributes - Ortscode_Geschoßbezeichnung: E02
 | H2 Ebene +2 | WI-VS | 1213Wa 0812970468 | yes | Codetext | m² | Trockenbauarbeiten | Wand | Installationswand | WI-VS | 0 | A | 7.5 | 1213HWa0812968105 | NEW | no | no | 0 | 0 | no | 0 | no | Codetext | AllplanAttributes - Ortscode_Geschoßbezeichnung: E02; W_Deckenanschluss: Gleitender Deckenanschluss Fall 03; ash_W_Trockenbau_Qualitäten: 18
 | H2 Ebene +2 | WI-HW 60 | 1213Wa 0812985925 | yes | Codetext | m² | Zimmer- und Holzbauarbeiten | Wand | Innenwand 1-Schalig | WI-HW 60 | 0 | A | 7.5 | 1213HWa0812968171 | NEW | yes | no | REI 30-A1 - D,s2-d0 +A1 | 0 | no | 0 | no | Codetext | AllplanAttributes - Ortscode_Geschoßbezeichnung: E02; ash W_laufende Nr. Statik: 1 (W 1.0/ 1.1/ 1.2)
 | H2 Ebene +2 | WI-LB | 1213Wa 0813196455 | yes | Codetext | m² | Trockenbauarbeiten | Wand | Innenwand 1-Schalig | WI-LB | 0 | A | 7.5 | 1213HWa0812968171 | NEW | no | no | REI 30-A1 - D,s2-d0 +A1 | 0 | no | 0 | no | Codetext | AllplanAttributes - Ortscode_Geschoßbezeichnung: E02; ash_W_Trockenbau_Qualitäten: 6
 | H2 Ebene +2 | WI-LB | 1213Wa 0813055525 | yes | Codetext | m² | Trockenbauarbeiten | Wand | Innenwand 1-Schalig | WI-LB | 0 | A | 7.5 | 1213HWa0813055509 | NEW | no | no | 0 | 0 | no | 0 | no | Codetext | AllplanAttributes - Ortscode_Geschoßbezeichnung: E02; ash_W_Trockenbau_Qualitäten: 6
 | H2 Ebene +2 | WI-LB | 1213Wa 0813054650 | yes | Codetext | m² | Trockenbauarbeiten | Wand | Innenwand 1-Schalig | WI-LB | 0 | A | 7.5 | 1213HWa0813054648 | NEW | no | no | 0 | 0 | no | 0 | no | Codetext | AllplanAttributes - Ortscode_Geschoßbezeichnung: E02; ash_W_Trockenbau_Qualitäten: 8
 | H2 Ebene +2 | Installationsraum | 1213Wa 0812970460 | yes | Codetext | m² | Trockenbauarbeiten | Wand | Installationswand | Installationsraum | 0 | A | 7.5 | 1213HWa0812968192 | NEW | no | no | 0 | 0 | no | 0 | no | Codetext | AllplanAttributes - Ortscode_Geschoßbezeichnung: E02
 | H2 Ebene +2 | WI-VS | 1213Wa 0812970466 | yes | Codetext | m² | Trockenbauarbeiten | Wand | Installationswand | WI-VS | 0 | A | 7.5 | 1213HWa0812968192 | NEW | no | no | 0 | 0 | no | 0 | no | Codetext | AllplanAttributes - Ortscode_Geschoßbezeichnung: E02; W_Deckenanschluss: Gleitender Deckenanschluss Fall 01; ash_W_Trockenbau_Qualitäten: 2
 | H2 Ebene +2 | WI-LB | 1213Wa 0813054630 | yes | Codetext | m² | Trockenbauarbeiten | Wand | Innenwand 1-Schalig | WI-LB | 0 | A | 7.5 | 1213HWa0813054629 | NEW | no | no | 0 | 0 | no | 0 | no | Codetext | AllplanAttributes - Ortscode_Geschoßbezeichnung: E02; ash_W_Trockenbau_Qualitäten: 8
 | H2 Ebene +2 | Installationsraum | 1213Wa 0812970454 | yes | Codetext | m² | Trockenbauarbeiten | Wand | Installationswand | Installationsraum | 0 | A | 7.5 | 1213HWa0812968054 | NEW | no | no | 0 | 0 | no | 0 | no | Codetext | AllplanAttributes - Ortscode_Geschoßbezeichnung: E02
 | H2 Ebene +2 | WI-VS | 1213Wa 0812971273 | yes | Codetext | m² | Trockenbauarbeiten | Wand | Installationswand | WI-VS | 0 | A | 7.5 | 1213HWa0812968054 | NEW | no | no | 0 | 0 | no | 0 | no | Codetext | AllplanAttributes - Ortscode_Geschoßbezeichnung: E02; W_Deckenanschluss: Gleitender Deckenanschluss Fall 01; ash_W_Trockenbau_Qualitäten: 2
 | H2 Ebene +2 | WI-LB | 1213Wa 0812970615 | yes | Codetext | m² | Trockenbauarbeiten | Wand | Innenwand 1-Schalig | WI-LB | 0 | A | 7.5 | 1213HWa0812968146 | NEW | no | no | 0 | 0 | no | 52 | no | Codetext | AllplanAttributes - Ortscode_Geschoßbezeichnung: E02; ash_W_Trockenbau_Qualitäten: 8; Sicherheitsklasse: -
 | H2 Ebene +2 | Installationsraum | 1213Wa 0813088336 | yes | Codetext | m² | Trockenbauarbeiten | Wand | Innenwand 1-Schalig | Installationsraum | 0 | A | 7.5 | 1213HWa0812968146 | NEW | no | no | 0 | 0 | no | 0 | no | Codetext | AllplanAttributes - Ortscode_Geschoßbezeichnung: E02; Sicherheitsklasse: -
 | H2 Ebene +2 | WI-HW 60 | 1213Wa 0813194900 | yes | Codetext | m² | Zimmer- und Holzbauarbeiten | Wand | Innenwand 1-Schalig | WI-HW 60 | 0 | A | 7.5 | 1213HWa0812968146 | NEW | no | no | 0 | 0 | no | 52 | no | Codetext | AllplanAttributes - Ortscode_Geschoßbezeichnung: E02; Sicherheitsklasse: -; ash W_laufende Nr. Statik: 3 (W 3.0)
 | H2 Ebene +2 | Installationsraum | 1213Wa 0812970456 | yes | Codetext | m² | Trockenbauarbeiten | Wand | Installationswand | Installationsraum | 0 | A | 7.5 | 1213HWa0812968049 | NEW | no | no | 0 | 0 | no | 0 | no | Codetext | AllplanAttributes - Ortscode_Geschoßbezeichnung: E02
 | H2 Ebene +2 | WI-VS | 1213Wa 0812970462 | yes | Codetext | m² | Trockenbauarbeiten | Wand | Installationswand | WI-VS | 0 | A | 7.5 | 1213HWa0812968049 | NEW | no | no | 0 | 0 | no | 0 | no | Codetext | AllplanAttributes - Ortscode_Geschoßbezeichnung: E02; W_Deckenanschluss: Gleitender Deckenanschluss Fall 01; ash_W_Trockenbau_Qualitäten: 2
 | H2 Ebene +2 | WI-LB | 1213Wa 0813054726 | yes | Codetext | m² | Trockenbauarbeiten | Wand | Innenwand 1-Schalig | WI-LB | 0 | A | 7.5 | 1213HWa0813054724 | NEW | no | no | 0 | 0 | no | 0 | no | Codetext | AllplanAttributes - Ortscode_Geschoßbezeichnung: E02; ash_W_Trockenbau_Qualitäten: 8
 | H2 Ebene +2 | WI-LB | 1213Wa 0812970945 | yes | Codetext | m² | Trockenbauarbeiten | Wand | Innenwand 1-Schalig | WI-LB | 0 | A | 7.5 | 1213HWa0812968112 | NEW | no | no | REI 60-A1 - D,s2-d0 +A1 | 0 | no | 47 | no | Codetext | AllplanAttributes - Ortscode_Geschoßbezeichnung: E02; ash_W_Trockenbau_Qualitäten: 1b
 | H2 Ebene +2 | WI-LB | 1213Wa 0812970368 | yes | Codetext | m² | Trockenbauarbeiten | Wand | Innenwand 1-Schalig | WI-LB | 0 | A | 7.5 | 1213HWa0812968266 | NEW | no | no | REI 60-A1 - D,s2-d0 /A1 | 0 | no | 0 | no | Codetext | AllplanAttributes - Ortscode_Geschoßbezeichnung: E02; ash_W_Trockenbau_Qualitäten: 13
 | H2 Ebene +2 | WI-LB | 1213Wa 0812970382 | yes | Codetext | m² | Trockenbauarbeiten | Wand | Innenwand 1-Schalig | WI-LB | 0 | A | 7.5 | 1213HWa0812968237 | NEW | no | no | REI 60-A1 - D,s2-d0 /A1 | 0 | no | 0 | no | Codetext | AllplanAttributes - Ortscode_Geschoßbezeichnung: E02; ash_W_Trockenbau_Qualitäten: 13
 | H2 Ebene +2 | Installationsraum | 1213Wa 0812981988 | yes | Codetext | m² | Trockenbauarbeiten | Wand | Installationswand | Installationsraum | 0 | A | 7.5 | 1213HWa0812971326 | NEW | no | no | 0 | 0 | no | 0 | no | Codetext | AllplanAttributes - Ortscode_Geschoßbezeichnung: E02
 | H2 Ebene +2 | WI-VS | 1213Wa 0812981986 | yes | Codetext | m² | Trockenbauarbeiten | Wand | Installationswand | WI-VS | 0 | A | 7.5 | 1213HWa0812971326 | NEW | no | no | 0 | 0 | no | 0 | no | Codetext | AllplanAttributes - Ortscode_Geschoßbezeichnung: E02; W_Deckenanschluss: Gleitender Deckenanschluss Fall 03; ash_W_Trockenbau_Qualitäten: 18
 | H2 Ebene +2 | WI-IW | 1213Wa 0813062198 | yes | Codetext | m² | Trockenbauarbeiten | Wand | Installationswand | WI-IW | 0 | A | 7.5 | 1213HWa0813062197 | NEW |  | no | 0 | 0 | no | 0 | no | Codetext | AllplanAttributes - Ortscode_Geschoßbezeichnung: E02; ash_W_Trockenbau_Qualitäten: 16
 | H2 Ebene +2 | WI-HW 60 | 1213Wa 0812986279 | yes | Codetext | m² | Zimmer- und Holzbauarbeiten | Wand | Innenwand 1-Schalig | WI-HW 60 | 0 | A | 7.5 | 1213HWa0812968118 | NEW | no | no | REI 30-A1 - D,s2-d0 +A1 | 0 | no | 0 | no | Codetext | AllplanAttributes - Ortscode_Geschoßbezeichnung: E02; ash W_laufende Nr. Statik: 3 (W 3.0)
 | H2 Ebene +2 | WI-LB | 1213Wa 0813098072 | yes | Codetext | m² | Trockenbauarbeiten | Wand | Innenwand 1-Schalig | WI-LB | 0 | A | 7.5 | 1213HWa0812968118 | NEW | no | no | REI 30-A1 - D,s2-d0 +A1 | 0 | no | 0 | no | Codetext | AllplanAttributes - Ortscode_Geschoßbezeichnung: E02; ash_W_Trockenbau_Qualitäten: 6
 | H2 Ebene +2 | Installationsraum | 1213Wa 0812970486 | yes | Codetext | m² | Trockenbauarbeiten | Wand | Installationswand | Installationsraum | 0 | A | 7.5 | 1213HWa0812968284 | NEW | no | no | 0 | 0 | no | 0 | no | Codetext | AllplanAttributes - Ortscode_Geschoßbezeichnung: E02
 | H2 Ebene +2 | WI-VS | 1213Wa 0812970488 | yes | Codetext | m² | Trockenbauarbeiten | Wand | Installationswand | WI-VS | 0 | A | 7.5 | 1213HWa0812968284 | NEW | no | no | 0 | 0 | no | 0 | no | Codetext | AllplanAttributes - Ortscode_Geschoßbezeichnung: E02; W_Deckenanschluss: Gleitender Deckenanschluss Fall 01; ash_W_Trockenbau_Qualitäten: 5
 | H2 Ebene +2 | WI-LB | 1213Wa 0812970344 | yes | Codetext | m² | Trockenbauarbeiten | Wand | Innenwand 1-Schalig | WI-LB | 0 | A | 7.5 | 1213HWa0812968333 | NEW | no | no | REI 60-A1 - D,s2-d0 /A1 | 0 | no | 0 | no | Codetext | AllplanAttributes - Ortscode_Geschoßbezeichnung: E02; ash_W_Trockenbau_Qualitäten: 13
 | H2 Ebene +2 | WI-LB | 1213Wa 0813411591 | yes | Codetext | m² | Trockenbauarbeiten | Wand | Innenwand 1-Schalig | WI-LB | 0 | A | 7.5 | 1213HWa0812968112 | NEW | no | no | REI 60-A1 - D,s2-d0 +A1 | 0 | no | 47 | no | Codetext | AllplanAttributes - Ortscode_Geschoßbezeichnung: E02; ash_W_Trockenbau_Qualitäten: 1b
 | H2 Ebene +2 | WI-LB | 1213Wa 0812970681 | yes | Codetext | m² | Trockenbauarbeiten | Wand | Innenwand 1-Schalig | WI-LB | 0 | A | 7.5 | 1213HWa0812968086 | NEW |  | no | 0 | 0 | no | 47 | no | Codetext | AllplanAttributes - Ortscode_Geschoßbezeichnung: E02; W_Deckenanschluss: Gleitender Deckenanschluss Fall 03; ash_W_Trockenbau_Qualitäten: 1c
 | H2 Ebene +2 | WI-LB | 1213Wa 0812970676 | yes | Codetext | m² | Trockenbauarbeiten | Wand | Innenwand 1-Schalig | WI-LB | 0 | A | 7.5 | 1213HWa0812968085 | NEW |  | no | 0 | 0 | no | 47 | no | Codetext | AllplanAttributes - Ortscode_Geschoßbezeichnung: E02; W_Deckenanschluss: Gleitender Deckenanschluss Fall 03; ash_W_Trockenbau_Qualitäten: 1c
 | H2 Ebene +2 | WI-LB | 1213Wa 0812970671 | yes | Codetext | m² | Trockenbauarbeiten | Wand | Innenwand 1-Schalig | WI-LB | 0 | A | 7.5 | 1213HWa0812968084 | NEW |  | no | 0 | 0 | no | 47 | no | Codetext | AllplanAttributes - Ortscode_Geschoßbezeichnung: E02; W_Deckenanschluss: Gleitender Deckenanschluss Fall 03; ash_W_Trockenbau_Qualitäten: 1c
 | H2 Ebene +2 | WI-HW 60 | 1213Wa 0812986416 | yes |  | m² | Zimmer- und Holzbauarbeiten | Wand | Innenwand 1-Schalig | WI-HW 60 |  |  | 7.5 | 1213HWa0812971211 | NEW | no | no | REI-M 60-D,s2,d0 + A1 |  |  | 47 | AllplanAttributes - Ortscode_Geschoßbezeichnung: E02; ash W_laufende Nr. Statik: 7 (W 6.0-1)
 | H2 Ebene +2 | WI-LB | 1213Wa 0813202483 | yes | Codetext | m² | Trockenbauarbeiten | Wand | Innenwand 1-Schalig | WI-LB | 0 | A | 7.5 | 1113HWa0812959982 | NEW | no | no | REI 60-A1 - D,s2-d0 /A1 | 0 | no | 47 | no | Codetext | AllplanAttributes - Ortscode_Geschoßbezeichnung: E02; ash_W_Trockenbau_Qualitäten: 6; Sicherheitsklasse: -
 | H2 Ebene +2 | WI-LB | 1213Wa 0813209472 | yes | Codetext | m² | Trockenbauarbeiten | Wand | Innenwand 1-Schalig | WI-LB | 0 | A | 7.5 | 1213HWa0813055490 | NEW | no | no | 0 | 0 | no | 0 | no | Codetext | AllplanAttributes - Ortscode_Geschoßbezeichnung: E02; ash_W_Trockenbau_Qualitäten: 18
 | H2 Ebene +2 | WI-LB | 1213Wa 0813215138 | yes | Codetext | m² | Trockenbauarbeiten | Wand | Innenwand 1-Schalig | WI-LB | 0 | A | 7.5 | 1213HWa0813055509 | NEW | no | no | 0 | 0 | no | 0 | no | Codetext | AllplanAttributes - Ortscode_Geschoßbezeichnung: E02; ash_W_Trockenbau_Qualitäten: 18
 | H2 Ebene +2 | WI-LB | 1213Wa 0812970332 | yes | Codetext | m² | Trockenbauarbeiten | Wand | Innenwand 1-Schalig | WI-LB | 0 | A | 7.5 | 1213HWa0812968365 | NEW | no | no | REI 60-A1 - D,s2-d0 /A1 | 0 | no | 0 | no | Codetext | AllplanAttributes - Ortscode_Geschoßbezeichnung: E02; ash_W_Trockenbau_Qualitäten: 13
 | H2 Ebene +2 | WI-HW 60 | 1213Wa 0812985946 | yes | Codetext | m² | Zimmer- und Holzbauarbeiten | Wand | Innenwand 1-Schalig | WI-HW 60 | 0 | A | 7.5 | 1213HWa0812968238 | NEW | no | no | REI 30 | 0 | no | 47 | no | Codetext | AllplanAttributes - Ortscode_Geschoßbezeichnung: E02; Sicherheitsklasse: -; ash W_laufende Nr. Statik: 1 (W 1.0/ 1.1/ 1.2)
 | H2 Ebene +2 | WI-LB | 1213Wa 0813090386 | yes | Codetext | m² | Trockenbauarbeiten | Wand | Innenwand 1-Schalig | WI-LB | 0 | A | 7.5 | 1213HWa0812968238 | NEW | no | no | REI 30-A1 - D,s2-d0 +A1 | 0 | no | 47 | no | Codetext | AllplanAttributes - Ortscode_Geschoßbezeichnung: E02; ash_W_Trockenbau_Qualitäten: 6; Sicherheitsklasse: -
 | H2 Ebene +2 | WI-HW 60 | 1213Wa 0813580117 | yes | Codetext | m² | Zimmer- und Holzbauarbeiten | Wand | Innenwand 1-Schalig | WI-HW 60 | 0 | A | 7.5 | 1213HWa0812968238 | NEW | no | no | REI 30 | 0 | no | 47 | no | Codetext | AllplanAttributes - Ortscode_Geschoßbezeichnung: E02; Sicherheitsklasse: -; ash W_laufende Nr. Statik: 1 (W 1.0/ 1.1/ 1.2)
 | H2 Ebene +2 | WI-LB | 1213Wa 0813580115 | yes | Codetext | m² | Trockenbauarbeiten | Wand | Innenwand 1-Schalig | WI-LB | 0 | A | 7.5 | 1213HWa0812968238 | NEW | no | no | REI 30-A1 - D,s2-d0 +A1 | 0 | no | 47 | no | Codetext | AllplanAttributes - Ortscode_Geschoßbezeichnung: E02; ash_W_Trockenbau_Qualitäten: 6; Sicherheitsklasse: -
 | H2 Ebene +2 | WI-HW 60 | 1213Wa 0813580884 | yes | Codetext | m² | Zimmer- und Holzbauarbeiten | Wand | Innenwand 1-Schalig | WI-HW 60 | 0 | A | 7.5 | 1213HWa0812968238 | NEW | no | no | REI 30 | 0 | no | 47 | no | Codetext | AllplanAttributes - Ortscode_Geschoßbezeichnung: E02; Sicherheitsklasse: -; ash W_laufende Nr. Statik: 1 (W 1.0/ 1.1/ 1.2)
 | H2 Ebene +2 | WI-LB | 1213Wa 0813580882 | yes | Codetext | m² | Trockenbauarbeiten | Wand | Innenwand 1-Schalig | WI-LB | 0 | A | 7.5 | 1213HWa0812968238 | NEW | no | no | REI 30-A1 - D,s2-d0 +A1 | 0 | no | 47 | no | Codetext | AllplanAttributes - Ortscode_Geschoßbezeichnung: E02; ash_W_Trockenbau_Qualitäten: 6; Sicherheitsklasse: -
 | H2 Ebene +2 | WI-HW 60 | 1213Wa 0813581429 | yes | Codetext | m² | Zimmer- und Holzbauarbeiten | Wand | Innenwand 1-Schalig | WI-HW 60 | 0 | A | 7.5 | 1213HWa0812968238 | NEW | no | no | REI 30 | 0 | no | 47 | no | Codetext | AllplanAttributes - Ortscode_Geschoßbezeichnung: E02; Sicherheitsklasse: -; ash W_laufende Nr. Statik: 1 (W 1.0/ 1.1/ 1.2)
 | H2 Ebene +2 | WI-LB | 1213Wa 0813581427 | yes | Codetext | m² | Trockenbauarbeiten | Wand | Innenwand 1-Schalig | WI-LB | 0 | A | 7.5 | 1213HWa0812968238 | NEW | no | no | REI 30-A1 - D,s2-d0 +A1 | 0 | no | 47 | no | Codetext | AllplanAttributes - Ortscode_Geschoßbezeichnung: E02; ash_W_Trockenbau_Qualitäten: 6; Sicherheitsklasse: -
 | H2 Ebene +2 | WI-HW 60 | 1213Wa 0812986616 | yes | Codetext | m² | Zimmer- und Holzbauarbeiten | Wand | Innenwand 1-Schalig | WI-HW 60 | 0 | A | 7.5 | 1213HWa0812968553 | NEW | no | no | REI 30 | 0 | no | 47 | no | Codetext | AllplanAttributes - Ortscode_Geschoßbezeichnung: E02; Sicherheitsklasse: -; ash W_laufende Nr. Statik: 1 (W 1.0/ 1.1/ 1.2)
 | H2 Ebene +2 | WI-LB | 1213Wa 0813089415 | yes | Codetext | m² | Trockenbauarbeiten | Wand | Innenwand 1-Schalig | WI-LB | 0 | A | 7.5 | 1213HWa0812968553 | NEW | no | no | REI 30-A1 - D,s2-d0 +A1 | 0 | no | 47 | no | Codetext | AllplanAttributes - Ortscode_Geschoßbezeichnung: E02; ash_W_Trockenbau_Qualitäten: 6; Sicherheitsklasse: -
 | H2 Ebene +2 | WI-HW 60 | 1213Wa 0813592932 | yes | Codetext | m² | Zimmer- und Holzbauarbeiten | Wand | Innenwand 1-Schalig | WI-HW 60 | 0 | A | 7.5 | 1213HWa0812968553 | NEW | no | no | REI 30 | 0 | no | 47 | no | Codetext | AllplanAttributes - Ortscode_Geschoßbezeichnung: E02; Sicherheitsklasse: -; ash W_laufende Nr. Statik: 1 (W 1.0/ 1.1/ 1.2)
 | H2 Ebene +2 | WI-LB | 1213Wa 0813592937 | yes | Codetext | m² | Trockenbauarbeiten | Wand | Innenwand 1-Schalig | WI-LB | 0 | A | 7.5 | 1213HWa0812968553 | NEW | no | no | REI 30-A1 - D,s2-d0 +A1 | 0 | no | 47 | no | Codetext | AllplanAttributes - Ortscode_Geschoßbezeichnung: E02; ash_W_Trockenbau_Qualitäten: 6; Sicherheitsklasse: -
 | H2 Ebene +2 | WI-HW 60 | 1213Wa 0813593942 | yes | Codetext | m² | Zimmer- und Holzbauarbeiten | Wand | Innenwand 1-Schalig | WI-HW 60 | 0 | A | 7.5 | 1213HWa0812968553 | NEW | no | no | REI 30 | 0 | no | 47 | no | Codetext | AllplanAttributes - Ortscode_Geschoßbezeichnung: E02; Sicherheitsklasse: -; ash W_laufende Nr. Statik: 1 (W 1.0/ 1.1/ 1.2)
 | H2 Ebene +2 | WI-LB | 1213Wa 0813593940 | yes | Codetext | m² | Trockenbauarbeiten | Wand | Innenwand 1-Schalig | WI-LB | 0 | A | 7.5 | 1213HWa0812968553 | NEW | no | no | REI 30-A1 - D,s2-d0 +A1 | 0 | no | 47 | no | Codetext | AllplanAttributes - Ortscode_Geschoßbezeichnung: E02; ash_W_Trockenbau_Qualitäten: 6; Sicherheitsklasse: -
 | H2 Ebene +2 | WI-HW 60 | 1213Wa 0813594503 | yes | Codetext | m² | Zimmer- und Holzbauarbeiten | Wand | Innenwand 1-Schalig | WI-HW 60 | 0 | A | 7.5 | 1213HWa0812968553 | NEW | no | no | REI 30 | 0 | no | 47 | no | Codetext | AllplanAttributes - Ortscode_Geschoßbezeichnung: E02; Sicherheitsklasse: -; ash W_laufende Nr. Statik: 1 (W 1.0/ 1.1/ 1.2)
 | H2 Ebene +2 | WI-LB | 1213Wa 0813594501 | yes | Codetext | m² | Trockenbauarbeiten | Wand | Innenwand 1-Schalig | WI-LB | 0 | A | 7.5 | 1213HWa0812968553 | NEW | no | no | REI 30-A1 - D,s2-d0 +A1 | 0 | no | 47 | no | Codetext | AllplanAttributes - Ortscode_Geschoßbezeichnung: E02; ash_W_Trockenbau_Qualitäten: 6; Sicherheitsklasse: -
 | H2 Ebene +2 | WI-HW 60 | 1213Wa 0813605031 | yes | Codetext | m² | Zimmer- und Holzbauarbeiten | Wand | Innenwand 1-Schalig | WI-HW 60 | 0 | A | 7.5 | 1213HWa0812968164 | NEW | no | no | REI 60-A1 - D,s2-d0 +A1 | 0 | no | 47 | no | Codetext | AllplanAttributes - Ortscode_Geschoßbezeichnung: E02; Sicherheitsklasse: -; ash W_laufende Nr. Statik: 1 (W 1.0/ 1.1/ 1.2)
 | H2 Ebene +2 | WI-LB | 1213Wa 0813605035 | yes | Codetext | m² | Trockenbauarbeiten | Wand | Innenwand 1-Schalig | WI-LB | 0 | A | 7.5 | 1213HWa0812968164 | NEW | no | no | REI 60-A1 - D,s2-d0 /A1 | 0 | no | 47 | no | Codetext | AllplanAttributes - Ortscode_Geschoßbezeichnung: E02; ash_W_Trockenbau_Qualitäten: 6; Sicherheitsklasse: -
 | H2 Ebene +2 | WI-HW 60 | 1213Wa 0812986209 | yes | Codetext | m² | Zimmer- und Holzbauarbeiten | Wand | Innenwand 1-Schalig | WI-HW 60 | 0 | A | 7.5 | 1213HWa0812968165 | NEW | no | no | REI 30 | 0 | no | 47 | no | Codetext | AllplanAttributes - Ortscode_Geschoßbezeichnung: E02; Sicherheitsklasse: -; ash W_laufende Nr. Statik: 1 (W 1.0/ 1.1/ 1.2)
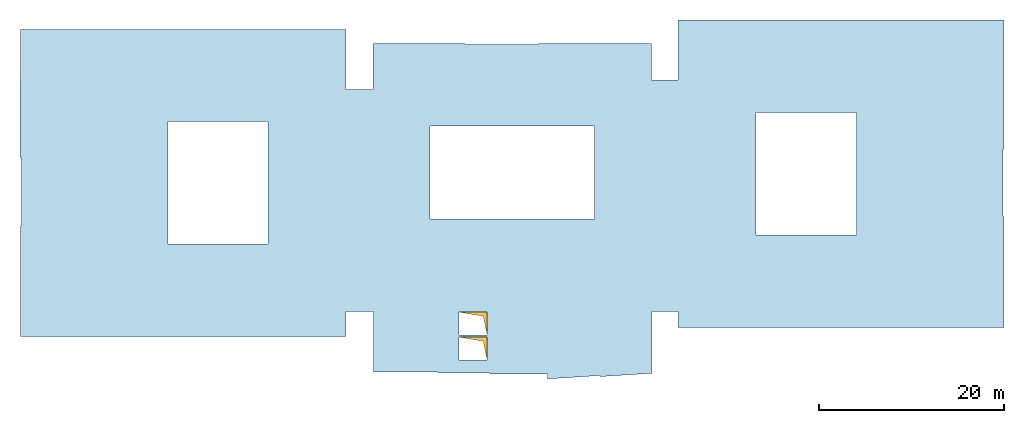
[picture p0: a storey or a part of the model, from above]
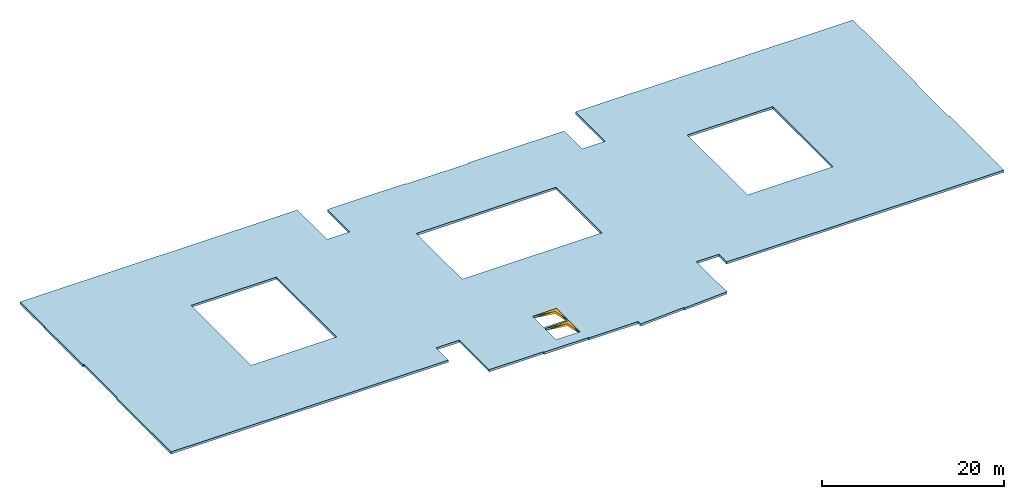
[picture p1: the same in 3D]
Properties of the parts of a building model (IFC4), part 56 of 80

# IfcWall (6826)
Name | In | Material | Allright_Bauteil_ID | 2D Interaktion | Codetext | Abrechnungsart | Gewerk | Objektname | Bezeichnung | AllplanAttributes, Material | Typ = SurfaceSpreadOfFlame | Brandschutzklasse | OKFF | P_ID | Status | LoadBearing | IsExternal | FireRating | ThermalTransmittance (W/K/m2) | Combustible | AcousticRating | Compartmentation | Reference
 | H2 Ebene +2 | WI-LB | 1213Wa 0813082944 | yes | Codetext | m² | Trockenbauarbeiten | Wand | Innenwand 1-Schalig | WI-LB | 0 | A | 7.5 | 1213HWa0812968165 | NEW | no | no | REI 30-A1 - D,s2-d0 +A1 | 0 | no | 47 | no | Codetext | AllplanAttributes - Ortscode_Geschoßbezeichnung: E02; ash_W_Trockenbau_Qualitäten: 6; Sicherheitsklasse: -
 | H2 Ebene +2 | WI-HW 60 | 1213Wa 0813622424 | yes | Codetext | m² | Zimmer- und Holzbauarbeiten | Wand | Innenwand 1-Schalig | WI-HW 60 | 0 | A | 7.5 | 1213HWa0812968165 | NEW | no | no | REI 30 | 0 | no | 47 | no | Codetext | AllplanAttributes - Ortscode_Geschoßbezeichnung: E02; Sicherheitsklasse: -; ash W_laufende Nr. Statik: 1 (W 1.0/ 1.1/ 1.2)
 | H2 Ebene +2 | WI-LB | 1213Wa 0813622421 | yes | Codetext | m² | Trockenbauarbeiten | Wand | Innenwand 1-Schalig | WI-LB | 0 | A | 7.5 | 1213HWa0812968165 | NEW | no | no | REI 30-A1 - D,s2-d0 +A1 | 0 | no | 47 | no | Codetext | AllplanAttributes - Ortscode_Geschoßbezeichnung: E02; ash_W_Trockenbau_Qualitäten: 6; Sicherheitsklasse: -
 | H2 Ebene +2 | WI-HW 60 | 1213Wa 0813623073 | yes | Codetext | m² | Zimmer- und Holzbauarbeiten | Wand | Innenwand 1-Schalig | WI-HW 60 | 0 | A | 7.5 | 1213HWa0812968165 | NEW | no | no | REI 30 | 0 | no | 47 | no | Codetext | AllplanAttributes - Ortscode_Geschoßbezeichnung: E02; Sicherheitsklasse: -; ash W_laufende Nr. Statik: 1 (W 1.0/ 1.1/ 1.2)
 | H2 Ebene +2 | WI-LB | 1213Wa 0813623071 | yes | Codetext | m² | Trockenbauarbeiten | Wand | Innenwand 1-Schalig | WI-LB | 0 | A | 7.5 | 1213HWa0812968165 | NEW | no | no | REI 30-A1 - D,s2-d0 +A1 | 0 | no | 47 | no | Codetext | AllplanAttributes - Ortscode_Geschoßbezeichnung: E02; ash_W_Trockenbau_Qualitäten: 6; Sicherheitsklasse: -
 | H2 Ebene +2 | WI-HW 60 | 1213Wa 0813623484 | yes | Codetext | m² | Zimmer- und Holzbauarbeiten | Wand | Innenwand 1-Schalig | WI-HW 60 | 0 | A | 7.5 | 1213HWa0812968165 | NEW | no | no | REI 30 | 0 | no | 47 | no | Codetext | AllplanAttributes - Ortscode_Geschoßbezeichnung: E02; Sicherheitsklasse: -; ash W_laufende Nr. Statik: 1 (W 1.0/ 1.1/ 1.2)
 | H2 Ebene +2 | WI-LB | 1213Wa 0813623482 | yes | Codetext | m² | Trockenbauarbeiten | Wand | Innenwand 1-Schalig | WI-LB | 0 | A | 7.5 | 1213HWa0812968165 | NEW | no | no | REI 30-A1 - D,s2-d0 +A1 | 0 | no | 47 | no | Codetext | AllplanAttributes - Ortscode_Geschoßbezeichnung: E02; ash_W_Trockenbau_Qualitäten: 6; Sicherheitsklasse: -
 | H2 Ebene +2 | WI-HW 60 | 1213Wa 0813635044 | yes | Codetext | m² | Zimmer- und Holzbauarbeiten | Wand | Innenwand 1-Schalig | WI-HW 60 | 0 | A | 7.5 | 1213HWa0812968176 | NEW | no | no | REI 30 | 0 | no | 47 | no | Codetext | AllplanAttributes - Ortscode_Geschoßbezeichnung: E02; Sicherheitsklasse: -; ash W_laufende Nr. Statik: 1 (W 1.0/ 1.1/ 1.2)
 | H2 Ebene +2 | WI-LB | 1213Wa 0813635049 | yes | Codetext | m² | Trockenbauarbeiten | Wand | Innenwand 1-Schalig | WI-LB | 0 | A | 7.5 | 1213HWa0812968176 | NEW | no | no | REI 30-A1 - D,s2-d0 +A1 | 0 | no | 47 | no | Codetext | AllplanAttributes - Ortscode_Geschoßbezeichnung: E02; ash_W_Trockenbau_Qualitäten: 6; Sicherheitsklasse: -
 | H2 Ebene +2 | WI-HW 60 | 1213Wa 0813636016 | yes | Codetext | m² | Zimmer- und Holzbauarbeiten | Wand | Innenwand 1-Schalig | WI-HW 60 | 0 | A | 7.5 | 1213HWa0812968176 | NEW | no | no | REI 30 | 0 | no | 47 | no | Codetext | AllplanAttributes - Ortscode_Geschoßbezeichnung: E02; Sicherheitsklasse: -; ash W_laufende Nr. Statik: 1 (W 1.0/ 1.1/ 1.2)
 | H2 Ebene +2 | WI-LB | 1213Wa 0813636014 | yes | Codetext | m² | Trockenbauarbeiten | Wand | Innenwand 1-Schalig | WI-LB | 0 | A | 7.5 | 1213HWa0812968176 | NEW | no | no | REI 30-A1 - D,s2-d0 +A1 | 0 | no | 47 | no | Codetext | AllplanAttributes - Ortscode_Geschoßbezeichnung: E02; ash_W_Trockenbau_Qualitäten: 6; Sicherheitsklasse: -
 | H2 Ebene +2 | WI-HW 60 | 1213Wa 0812986194 | yes | Codetext | m² | Zimmer- und Holzbauarbeiten | Wand | Innenwand 1-Schalig | WI-HW 60 | 0 | A | 7.5 | 1213HWa0812968176 | NEW | no | no | REI 30 | 0 | no | 47 | no | Codetext | AllplanAttributes - Ortscode_Geschoßbezeichnung: E02; Sicherheitsklasse: -; ash W_laufende Nr. Statik: 1 (W 1.0/ 1.1/ 1.2)
 | H2 Ebene +2 | WI-LB | 1213Wa 0813082013 | yes | Codetext | m² | Trockenbauarbeiten | Wand | Innenwand 1-Schalig | WI-LB | 0 | A | 7.5 | 1213HWa0812968176 | NEW | no | no | REI 30-A1 - D,s2-d0 +A1 | 0 | no | 47 | no | Codetext | AllplanAttributes - Ortscode_Geschoßbezeichnung: E02; ash_W_Trockenbau_Qualitäten: 6; Sicherheitsklasse: -
 | H2 Ebene +2 | WI-HW 60 | 1213Wa 0813636644 | yes | Codetext | m² | Zimmer- und Holzbauarbeiten | Wand | Innenwand 1-Schalig | WI-HW 60 | 0 | A | 7.5 | 1213HWa0812968176 | NEW | no | no | REI 30 | 0 | no | 47 | no | Codetext | AllplanAttributes - Ortscode_Geschoßbezeichnung: E02; Sicherheitsklasse: -; ash W_laufende Nr. Statik: 1 (W 1.0/ 1.1/ 1.2)
 | H2 Ebene +2 | WI-LB | 1213Wa 0813636642 | yes | Codetext | m² | Trockenbauarbeiten | Wand | Innenwand 1-Schalig | WI-LB | 0 | A | 7.5 | 1213HWa0812968176 | NEW | no | no | REI 30-A1 - D,s2-d0 +A1 | 0 | no | 47 | no | Codetext | AllplanAttributes - Ortscode_Geschoßbezeichnung: E02; ash_W_Trockenbau_Qualitäten: 6; Sicherheitsklasse: -
 | H2 Ebene +2 | WI-HW 60 | 1213Wa 0813636833 | yes | Codetext | m² | Zimmer- und Holzbauarbeiten | Wand | Innenwand 1-Schalig | WI-HW 60 | 0 | A | 7.5 | 1213HWa0812968138 | NEW | no | no | REI 60-A1 - D,s2-d0 +A1 | 0 | no | 47 | no | Codetext | AllplanAttributes - Ortscode_Geschoßbezeichnung: E02; Sicherheitsklasse: -; ash W_laufende Nr. Statik: 1 (W 1.0/ 1.1/ 1.2)
 | H2 Ebene +2 | WI-LB | 1213Wa 0812970490 | yes | Codetext | m² | Trockenbauarbeiten | Wand | Außenwand 1-Schalig | WI-LB | 0 | A | 7.5 | 1213HWa0812968488 | NEW | no | no | REI 60-A1 - D,s2-d0 /A1 | 0 | no |  | no | Codetext | AllplanAttributes - Ortscode_Geschoßbezeichnung: E02; ash_W_Trockenbau_Qualitäten: 9
 | H2 Ebene +2 | WI-STB | 1213Wa 0812970493 | yes | Codetext | m² | Betonarbeiten | Wand | Außenwand 1-Schalig | WI-STB | 0 | A | 7.5 | 1213HWa0812968488 | NEW | yes | no | REI 60-A1 - D,s2-d0 /A1 | 0 | no | 52 | no | Codetext | AllplanAttributes - Ortscode_Geschoßbezeichnung: E02
 | H2 Ebene +2 | WI-LB | 1213Wa 0812970348 | yes | Codetext | m² | Trockenbauarbeiten | Wand | Innenwand 1-Schalig | WI-LB | 0 | A | 7.5 | 1213HWa0812968493 | NEW | no | no | REI 60-A1 - D,s2-d0 /A1 | 0 | no | 0 | no | Codetext | AllplanAttributes - Ortscode_Geschoßbezeichnung: E02; ash_W_Trockenbau_Qualitäten: 9
 | H2 Ebene +2 | WI-LB | 1213Wa 0812970346 | yes | Codetext | m² | Trockenbauarbeiten | Wand | Innenwand 1-Schalig | WI-LB | 0 | A | 7.5 | 1213HWa0812968491 | NEW | no | no | REI 60-A1 - D,s2-d0 /A1 | 0 | no |  | no | Codetext | AllplanAttributes - Ortscode_Geschoßbezeichnung: E02; ash_W_Trockenbau_Qualitäten: 9
 | H2 Ebene +2 | WI-LB | 1213Wa 0812970174 | yes | Codetext | m² | Trockenbauarbeiten | Wand | Innenwand 1-Schalig | WI-LB | 0 | A | 7.5 | 1213HWa0812968447 | NEW | no | no | REI 60-A1 - D,s2-d0 /A1 | 0 | no | 0 | no | Codetext | AllplanAttributes - Ortscode_Geschoßbezeichnung: E02
 | H2 Ebene +2 | WI-HW 60 | 1213Wa 0813479922 | yes | Codetext | m² | Zimmer- und Holzbauarbeiten | Wand | Innenwand 1-Schalig | WI-HW 60 | 0 | A | 7.5 | 1213HWa0812968537 | NEW | no | no | REI 60-A1 - D,s2-d0 /A1 | 0 | no | 0 | no | Codetext | AllplanAttributes - Ortscode_Geschoßbezeichnung: E02; ash W_laufende Nr. Statik: 3 (W 3.0)
 | H2 Ebene +2 | WI-LB | 1213Wa 0812970532 | yes | Codetext | m² | Trockenbauarbeiten | Wand | Innenwand 1-Schalig | WI-LB | 0 | A | 7.5 | 1213HWa0812968438 | NEW | no | no | REI 60-A1 - D,s2-d0 /A1 | 0 | no |  | no | Codetext | AllplanAttributes - Ortscode_Geschoßbezeichnung: E02; ash_W_Trockenbau_Qualitäten: 9
 | H2 Ebene +2 | WI-LB | 1213Wa 0812970409 | yes | Codetext | m² | Trockenbauarbeiten | Wand | Innenwand 1-Schalig | WI-LB | 0 | A | 7.5 | 1213HWa0812968458 | NEW | no | no | REI 60-A1 - D,s2-d0 /A1 | 0 | no |  | no | Codetext | AllplanAttributes - Ortscode_Geschoßbezeichnung: E02; ash_W_Trockenbau_Qualitäten: 9
 | H2 Ebene +2 | WI-LB | 1213Wa 0812970511 | yes | Codetext | m² | Trockenbauarbeiten | Wand | Innenwand 1-Schalig | WI-LB | 0 | A | 7.5 | 1213HWa0812968277 | NEW | no | no | REI 60-A1 - D,s2-d0 /A1 | 0 | no |  | no | Codetext | AllplanAttributes - Ortscode_Geschoßbezeichnung: E02
 | H2 Ebene +2 | WI-LB | 1213Wa 0812970478 | yes | Codetext | m² | Trockenbauarbeiten | Wand | Innenwand 1-Schalig | WI-LB | 0 | A | 7.5 | 1213HWa0812968504 | NEW | no | no | REI 60-A1 - D,s2-d0 /A1 | 0 | no | 0 | no | Codetext | AllplanAttributes - Ortscode_Geschoßbezeichnung: E02; ash_W_Trockenbau_Qualitäten: 9
 | H2 Ebene +2 | WI-LB | 1213Wa 0812970387 | yes | Codetext | m² | Trockenbauarbeiten | Wand | Innenwand 1-Schalig | WI-LB | 0 | A | 7.5 | 1213HWa0812968436 | NEW | no | no | REI 60-A1 - D,s2-d0 /A1 | 0 | no | 0 | no | Codetext | AllplanAttributes - Ortscode_Geschoßbezeichnung: E02; ash_W_Trockenbau_Qualitäten: 9
 | H2 Ebene +2 | WI-LB | 1213Wa 0812970411 | yes | Codetext | m² | Trockenbauarbeiten | Wand | Innenwand 1-Schalig | WI-LB | 0 | A | 7.5 | 1213HWa0812968457 | NEW | no | no | REI 60-A1 - D,s2-d0 /A1 | 0 | no |  | no | Codetext | AllplanAttributes - Ortscode_Geschoßbezeichnung: E02; ash_W_Trockenbau_Qualitäten: 9
 | H2 Ebene +2 | WI-LB | 1213Wa 0812970534 | yes | Codetext | m² | Trockenbauarbeiten | Wand | Innenwand 1-Schalig | WI-LB | 0 | A | 7.5 | 1213HWa0812968437 | NEW | no | no | REI 60-A1 - D,s2-d0 /A1 | 0 | no |  | no | Codetext | AllplanAttributes - Ortscode_Geschoßbezeichnung: E02; ash_W_Trockenbau_Qualitäten: 9
 | H2 Ebene +2 | WI-LB | 1213Wa 0812970526 | yes | Codetext | m² | Trockenbauarbeiten | Wand | Innenwand 1-Schalig | WI-LB | 0 | A | 7.5 | 1213HWa0812968442 | NEW | no | no | REI 60-A1 - D,s2-d0 /A1 | 0 | no | 52 | no | Codetext | AllplanAttributes - Ortscode_Geschoßbezeichnung: E02; ash_W_Trockenbau_Qualitäten: 9
 | H2 Ebene +2 | WI-LB | 1213Wa 0812970530 | yes | Codetext | m² | Trockenbauarbeiten | Wand | Innenwand 1-Schalig | WI-LB | 0 | A | 7.5 | 1213HWa0812968441 | NEW | no | no | REI 60-A1 - D,s2-d0 /A1 | 0 | no | 52 | no | Codetext | AllplanAttributes - Ortscode_Geschoßbezeichnung: E02; ash_W_Trockenbau_Qualitäten: 9
 | H2 Ebene +2 | WI-LB | 1213Wa 0812970376 | yes | Codetext | m² | Trockenbauarbeiten | Wand | Innenwand 1-Schalig | WI-LB | 0 | A | 7.5 | 1213HWa0812968446 | NEW | no | no | REI 60-A1 - D,s2-d0 /A1 | 0 | no | 0 | no | Codetext | AllplanAttributes - Ortscode_Geschoßbezeichnung: E02; ash_W_Trockenbau_Qualitäten: 9
 | H2 Ebene +2 | WI-LB | 1213Wa 0812970154 | yes | Codetext | m² | Trockenbauarbeiten | Wand | Innenwand 1-Schalig | WI-LB | 0 | A | 7.5 | 1213HWa0812968454 | NEW | no | no | REI 60-A1 - D,s2-d0 /A1 | 0 | no | 0 | no | Codetext | AllplanAttributes - Ortscode_Geschoßbezeichnung: E02; ash_W_Trockenbau_Qualitäten: 9
 | H2 Ebene +2 | WI-LB | 1213Wa 0812970520 | yes | Codetext | m² | Trockenbauarbeiten | Wand | Innenwand 1-Schalig | WI-LB | 0 | A | 7.5 | 1213HWa0812968453 | NEW | no | no | REI 60-A1 - D,s2-d0 /A1 | 0 | no | 0 | no | Codetext | AllplanAttributes - Ortscode_Geschoßbezeichnung: E02; ash_W_Trockenbau_Qualitäten: 9
 | H2 Ebene +2 | WI-STB | 1213Wa 0812969976 | yes | Codetext | m² | Zimmer- und Holzbauarbeiten | Wand | Innenwand 1-Schalig | WI-STB | 0 | A | 7.5 | 1213HWa0812968453 | NEW | yes | no | REI-M 60-A1 | 0 | no | 0 | no | Codetext | AllplanAttributes - Ortscode_Geschoßbezeichnung: E02
 | H2 Ebene +2 | WI-LB | 1213Wa 0812969942 | yes | Codetext | m² | Trockenbauarbeiten | Wand | Innenwand 1-Schalig | WI-LB | 0 | A | 7.5 | 1213HWa0812968507 | NEW | no | no | REI 60-A1 - D,s2-d0 /A1 | 0 | no | 0 | no | Codetext | AllplanAttributes - Ortscode_Geschoßbezeichnung: E02; ash_W_Trockenbau_Qualitäten: 9
 | H2 Ebene +2 | WI-LB | 1213Wa 0812969947 | yes | Codetext | m² | Trockenbauarbeiten | Wand | Innenwand 1-Schalig | WI-LB | 0 | A | 7.5 | 1213HWa0812968468 | NEW | no | no | REI 60-A1 - D,s2-d0 /A1 | 0 | no | 0 | no | Codetext | AllplanAttributes - Ortscode_Geschoßbezeichnung: E02; ash_W_Trockenbau_Qualitäten: 9
 | H2 Ebene +2 | WI-LB | 1213Wa 0812970188 | yes | Codetext | m² | Trockenbauarbeiten | Wand | Innenwand 1-Schalig | WI-LB | 0 | A | 7.5 | 1213HWa0812968449 | NEW | no | no | REI 60-A1 - D,s2-d0 /A1 | 0 | no | 0 | no | Codetext | AllplanAttributes - Ortscode_Geschoßbezeichnung: E02; ash_W_Trockenbau_Qualitäten: 9
 | H2 Ebene +2 | WI-STB | 1213Wa 0812970195 | yes | Codetext | m² | Zimmer- und Holzbauarbeiten | Wand | Innenwand 1-Schalig | WI-STB | 0 | A | 7.5 | 1213HWa0812968449 | NEW | yes | no | REI-M 60-A1 | 0 | no | 0 | no | Codetext | AllplanAttributes - Ortscode_Geschoßbezeichnung: E02; ash D_Detailverweis: Lösch; ash D_Plannummer: 1682
 | H2 Ebene +2 | WI-LB | 1213Wa 0812971219 | yes | Codetext | m² | Trockenbauarbeiten | Wand | Innenwand 1-Schalig | WI-LB | 0 | A | 7.5 | 1213HWa0812968158 | NEW | no | no | REI 60-A1 - D,s2-d0 /A1 | 0 | no | 52 | no | Codetext | AllplanAttributes - Ortscode_Geschoßbezeichnung: E02; ash_W_Trockenbau_Qualitäten: 6; Sicherheitsklasse: -
 | H2 Ebene +2 | Installationsraum | 1213Wa 0813086661 | yes | Codetext | m² | Trockenbauarbeiten | Wand | Innenwand 1-Schalig | Installationsraum | 0 | A | 7.5 | 1213HWa0812968158 | NEW | no | no | 0 | 0 | no | 0 | no | Codetext | AllplanAttributes - Ortscode_Geschoßbezeichnung: E02; Sicherheitsklasse: -
 | H2 Ebene +2 | WI-HW 60 | 1213Wa 0813086662 | yes | Codetext | m² | Zimmer- und Holzbauarbeiten | Wand | Innenwand 1-Schalig | WI-HW 60 | 0 | A | 7.5 | 1213HWa0812968158 | NEW | no | no | REI 60-A1 - D,s2-d0 +A1 | 0 | no | 52 | no | Codetext | AllplanAttributes - Ortscode_Geschoßbezeichnung: E02; Sicherheitsklasse: -; ash W_laufende Nr. Statik: 3 (W 3.0)
 | H2 Ebene +2 | WI-LB | 1213Wa 0812970413 | yes | Codetext | m² | Trockenbauarbeiten | Wand | Innenwand 1-Schalig | WI-LB | 0 | A | 7.5 | 1213HWa0812968102 | NEW | no | no | REI 60-A1 - D,s2-d0 /A1 | 0 | no | 52 | no | Codetext | AllplanAttributes - Ortscode_Geschoßbezeichnung: E02; ash_W_Trockenbau_Qualitäten: 6; Sicherheitsklasse: -
 | H2 Ebene +2 | WI-HW 60 | 1213Wa 0813087701 | yes | Codetext | m² | Zimmer- und Holzbauarbeiten | Wand | Innenwand 1-Schalig | WI-HW 60 | 0 | A | 7.5 | 1213HWa0812968102 | NEW | no | no | REI 60-A1 - D,s2-d0 +A1 | 0 | no | 52 | no | Codetext | AllplanAttributes - Ortscode_Geschoßbezeichnung: E02; Sicherheitsklasse: -; ash W_laufende Nr. Statik: 3 (W 3.0)
 | H2 Ebene +2 | WI-LB | 1213Wa 0812970396 | yes | Codetext | m² | Trockenbauarbeiten | Wand | Innenwand 1-Schalig | WI-LB | 0 | A | 7.5 | 1213HWa0812968162 | NEW | no | no | REI 60-A1 - D,s2-d0 /A1 | 0 | no | 52 | no | Codetext | AllplanAttributes - Ortscode_Geschoßbezeichnung: E02; ash_W_Trockenbau_Qualitäten: 6; Sicherheitsklasse: -
 | H2 Ebene +2 | WI-HW 60 | 1213Wa 0813087440 | yes | Codetext | m² | Zimmer- und Holzbauarbeiten | Wand | Innenwand 1-Schalig | WI-HW 60 | 0 | A | 7.5 | 1213HWa0812968162 | NEW | no | no | REI 60-A1 - D,s2-d0 +A1 | 0 | no | 52 | no | Codetext | AllplanAttributes - Ortscode_Geschoßbezeichnung: E02; Sicherheitsklasse: -; ash W_laufende Nr. Statik: 3 (W 3.0)
 | H2 Ebene +2 | WI-LB | 1213Wa 0812985908 | yes | Codetext | m² | Trockenbauarbeiten | Wand | Innenwand 1-Schalig | WI-LB | 0 | A | 7.5 | 1213HWa0812968151 | NEW | no | no | REI 60-A1 - D,s2-d0 /A1 | 0 | no | 52 | no | Codetext | AllplanAttributes - Ortscode_Geschoßbezeichnung: E02; ash_W_Trockenbau_Qualitäten: 6; Sicherheitsklasse: -
 | H2 Ebene +2 | Installationsraum | 1213Wa 0813087773 | yes | Codetext | m² | Trockenbauarbeiten | Wand | Innenwand 1-Schalig | Installationsraum | 0 | A | 7.5 | 1213HWa0812968151 | NEW | no | no | 0 | 0 | no | 0 | no | Codetext | AllplanAttributes - Ortscode_Geschoßbezeichnung: E02; Sicherheitsklasse: -
 | H2 Ebene +2 | WI-HW 60 | 1213Wa 0813099003 | yes | Codetext | m² | Zimmer- und Holzbauarbeiten | Wand | Innenwand 1-Schalig | WI-HW 60 | 0 | A | 7.5 | 1213HWa0812968151 | NEW | no | no | REI 60-A1 - D,s2-d0 +A1 | 0 | no | 52 | no | Codetext | AllplanAttributes - Ortscode_Geschoßbezeichnung: E02; Sicherheitsklasse: -; ash W_laufende Nr. Statik: 3 (W 3.0)
 | H2 Ebene +2 | WI-LB | 1213Wa 0812970553 | yes | Codetext | m² | Trockenbauarbeiten | Wand | Innenwand 1-Schalig | WI-LB | 0 | A | 7.5 | 1213HWa0812968147 | NEW | no | no | REI 60-A1 - D,s2-d0 /A1 | 0 | no | 52 | no | Codetext | AllplanAttributes - Ortscode_Geschoßbezeichnung: E02; ash_W_Trockenbau_Qualitäten: 6; Sicherheitsklasse: -
 | H2 Ebene +2 | WI-HW 60 | 1213Wa 0813195295 | yes |  | m² | Zimmer- und Holzbauarbeiten | Wand | Innenwand 1-Schalig | WI-HW 60 |  |  | 7.5 | 1213HWa0812968147 | NEW | no | no | REI-M 60-D,s2,d0 + A1 |  |  | 52 | AllplanAttributes - Ortscode_Geschoßbezeichnung: E02; ash W_laufende Nr. Statik: 7 (W 6.0-1)
 | H2 Ebene +2 | WI-LB | 1213Wa 0812971244 | yes | Codetext | m² | Trockenbauarbeiten | Wand | Innenwand 1-Schalig | WI-LB | 0 | A | 7.5 | 1113HWa0812959982 | NEW | no | no | REI 60-A1 - D,s2-d0 /A1 | 0 | no | 0 | no | Codetext | AllplanAttributes - Ortscode_Geschoßbezeichnung: E02; ash_W_Trockenbau_Qualitäten: 6; Sicherheitsklasse: -
 | H2 Ebene +2 | WI-HW 60 | 1213Wa 0813202536 | yes | Codetext | m² | Zimmer- und Holzbauarbeiten | Wand | Innenwand 1-Schalig | WI-HW 60 | 0 | A | 7.5 | 1213HWa0812968155 | NEW | yes | no | REI 60-A1 - D,s2-d0 +A1 | 0 | no | 47 | no | Codetext | AllplanAttributes - Ortscode_Geschoßbezeichnung: E02; ash W_laufende Nr. Statik: 7 (W 6.0-1)
 | H2 Ebene +2 | WI-LB | 1213Wa 0812970212 | yes | Codetext | m² | Trockenbauarbeiten | Wand | Außenwand 1-Schalig | WI-LB | 0 | A | 7.5 | 1213HWa0812968522 | NEW | no | no | REI 60-A1 - D,s2-d0 /A1 | 0 | no | 0 | no | Codetext | AllplanAttributes - Ortscode_Geschoßbezeichnung: E02; ash_W_Trockenbau_Qualitäten: 9
 | H2 Ebene +2 | WI-STB | 1213Wa 0812970210 | yes | Codetext | m² | Zimmer- und Holzbauarbeiten | Wand | Außenwand 1-Schalig | WI-STB | 0 | A | 7.5 | 1213HWa0812968522 | NEW | yes | no | REI-M 60-A1 | 0 | no | 0 | no | Codetext | AllplanAttributes - Ortscode_Geschoßbezeichnung: E02
 | H2 Ebene +2 | WI-LB | 1213Wa 0812970962 | yes | Codetext | m² | Trockenbauarbeiten | Wand | Innenwand 1-Schalig | WI-LB | 0 | A | 7.5 | 1213HWa0812968527 | NEW | no | no | REI 60-A1 - D,s2-d0 /A1 | 0 | no | 0 | no | Codetext | AllplanAttributes - Ortscode_Geschoßbezeichnung: E02
 | H2 Ebene +2 | WI-LB | 1213Wa 0812970169 | yes | Codetext | m² | Trockenbauarbeiten | Wand | Innenwand 1-Schalig | WI-LB | 0 | A | 7.5 | 1213HWa0812968546 | NEW | no | no | REI 60-A1 - D,s2-d0 /A1 | 0 | no | 0 | no | Codetext | AllplanAttributes - Ortscode_Geschoßbezeichnung: E02
 | H2 Ebene +2 | WI-HW 60 | 1213Wa 0813480918 | yes | Codetext | m² | Zimmer- und Holzbauarbeiten | Wand | Innenwand 1-Schalig | WI-HW 60 | 0 | A | 7.5 | 1213HWa0812968531 | NEW | no | no | REI 60-A1 - D,s2-d0 /A1 | 0 | no | 0 | no | Codetext | AllplanAttributes - Ortscode_Geschoßbezeichnung: E02
 | H2 Ebene +2 | WI-LB | 1213Wa 0812970495 | yes | Codetext | m² | Trockenbauarbeiten | Wand | Innenwand 1-Schalig | WI-LB | 0 | A | 7.5 | 1213HWa0812968486 | NEW | no | no | REI 60-A1 - D,s2-d0 /A1 | 0 | no |  | no | Codetext | AllplanAttributes - Ortscode_Geschoßbezeichnung: E02; ash_W_Trockenbau_Qualitäten: 9
 | H2 Ebene +2 | WI-LB | 1213Wa 0812971268 | yes | Codetext | m² | Trockenbauarbeiten | Wand | Innenwand 1-Schalig | WI-LB | 0 | A | 7.5 | 1213HWa0812968523 | NEW | no | no | REI 60-A1 - D,s2-d0 /A1 | 0 | no | 0 | no | Codetext | AllplanAttributes - Ortscode_Geschoßbezeichnung: E02; ash_W_Trockenbau_Qualitäten: 9
 | H2 Ebene +2 | WI-LB | 1213Wa 0812970497 | yes | Codetext | m² | Trockenbauarbeiten | Wand | Außenwand 1-Schalig | WI-LB | 0 | A | 7.5 | 1213HWa0812968481 | NEW | no | no | REI 60-A1 - D,s2-d0 /A1 | 0 | no |  | no | Codetext | AllplanAttributes - Ortscode_Geschoßbezeichnung: E02; ash_W_Trockenbau_Qualitäten: 9
 | H2 Ebene +2 | WI-STB | 1213Wa 0812970500 | yes | Codetext | m² | Zimmer- und Holzbauarbeiten | Wand | Außenwand 1-Schalig | WI-STB | 0 | A | 7.5 | 1213HWa0812968481 | NEW | yes | no | REI 60-A1 - D,s2-d0 /A1 | 0 | no | 47 | no | Codetext | AllplanAttributes - Ortscode_Geschoßbezeichnung: E02
 | H2 Ebene +2 | WI-LB | 1213Wa 0812970334 | yes | Codetext | m² | Trockenbauarbeiten | Wand | Innenwand 1-Schalig | WI-LB | 0 | A | 7.5 | 1213HWa0812968484 | NEW | no | no | REI 60-A1 - D,s2-d0 /A1 | 0 | no | 0 | no | Codetext | AllplanAttributes - Ortscode_Geschoßbezeichnung: E02; ash_W_Trockenbau_Qualitäten: 9
 | H2 Ebene +2 | WI-LB | 1213Wa 0812970203 | yes | Codetext | m² | Trockenbauarbeiten | Wand | Innenwand 1-Schalig | WI-LB | 0 | A | 7.5 | 1213HWa0812968525 | NEW | no | no | REI 60-A1 - D,s2-d0 /A1 | 0 | no | 0 | no | Codetext | AllplanAttributes - Ortscode_Geschoßbezeichnung: E02; ash_W_Trockenbau_Qualitäten: 9
 | H2 Ebene +2 | WI-LB | 1213Wa 0813404599 | yes | Codetext | m² | Trockenbauarbeiten | Wand | Innenwand 1-Schalig | WI-LB | 0 | A | 7.5 | 1213HWa0812968322 | NEW | no | no | REI 60-A1 - D,s2-d0 /A1 | 0 | no | 47 | no | Codetext | AllplanAttributes - Ortscode_Geschoßbezeichnung: E02; ash_W_Trockenbau_Qualitäten: 6; Sicherheitsklasse: -
 | H2 Ebene +2 | WI-HW 60 | 1213Wa 0813404602 | yes | Codetext | m² | Zimmer- und Holzbauarbeiten | Wand | Innenwand 1-Schalig | WI-HW 60 | 0 | A | 7.5 | 1213HWa0812968322 | NEW | no | no | REI 60-A1 - D,s2-d0 +A1 | 0 | no | 47 | no | Codetext | AllplanAttributes - Ortscode_Geschoßbezeichnung: E02; Sicherheitsklasse: -; ash W_laufende Nr. Statik: 3 (W 3.0)
 | H2 Ebene +2 | WI-LB | 1213Wa 0813240155 | yes | Codetext | m² | Trockenbauarbeiten | Wand | Innenwand 1-Schalig | WI-LB | 0 | A | 7.5 | 1213HWa0812968187 | NEW | no | no | REI 30-A1 - D,s2-d0 +A1 | 0 | no | 47 | no | Codetext | AllplanAttributes - Ortscode_Geschoßbezeichnung: E02; ash_W_Trockenbau_Qualitäten: 8; Sicherheitsklasse: -
 | H2 Ebene +2 | Installationsraum | 1213Wa 0813240159 | yes | Codetext | m² | Trockenbauarbeiten | Wand | Innenwand 1-Schalig | Installationsraum | 0 | A | 7.5 | 1213HWa0812968187 | NEW | no | no | 0 | 0 | no | 47 | no | Codetext | AllplanAttributes - Ortscode_Geschoßbezeichnung: E02; Sicherheitsklasse: -
 | H2 Ebene +2 | WI-HW 60 | 1213Wa 0813240154 | yes | Codetext | m² | Zimmer- und Holzbauarbeiten | Wand | Innenwand 1-Schalig | WI-HW 60 | 0 | A | 7.5 | 1213HWa0812968187 | NEW | no | no | REI 30-A1 - D,s2-d0 +A1 | 0 | no | 47 | no | Codetext | AllplanAttributes - Ortscode_Geschoßbezeichnung: E02; Sicherheitsklasse: -; ash W_laufende Nr. Statik: 3 (W 3.0)
 | H2 Ebene +2 | WI-LB | 1213Wa 0813245403 | yes | Codetext | m² | Trockenbauarbeiten | Wand | Innenwand 1-Schalig | WI-LB | 0 | A | 7.5 | 1213HWa0812968187 | NEW | no | no | REI 30-A1 - D,s2-d0 +A1 | 0 | no | 47 | no | Codetext | AllplanAttributes - Ortscode_Geschoßbezeichnung: E02; ash_W_Trockenbau_Qualitäten: 8; Sicherheitsklasse: -
 | H2 Ebene +2 | Installationsraum | 1213Wa 0813245402 | yes | Codetext | m² | Trockenbauarbeiten | Wand | Innenwand 1-Schalig | Installationsraum | 0 | A | 7.5 | 1213HWa0812968187 | NEW | no | no | 0 | 0 | no | 47 | no | Codetext | AllplanAttributes - Ortscode_Geschoßbezeichnung: E02; Sicherheitsklasse: -
 | H2 Ebene +2 | WI-HW 60 | 1213Wa 0813245405 | yes | Codetext | m² | Zimmer- und Holzbauarbeiten | Wand | Innenwand 1-Schalig | WI-HW 60 | 0 | A | 7.5 | 1213HWa0812968187 | NEW | no | no | REI 30-A1 - D,s2-d0 +A1 | 0 | no | 47 | no | Codetext | AllplanAttributes - Ortscode_Geschoßbezeichnung: E02; Sicherheitsklasse: -; ash W_laufende Nr. Statik: 3 (W 3.0)
 | H2 Ebene +2 | WI-LB | 1213Wa 0813239222 | yes | Codetext | m² | Trockenbauarbeiten | Wand | Innenwand 1-Schalig | WI-LB | 0 | A | 7.5 | 1213HWa0812968187 | NEW | no | no | REI 30-A1 - D,s2-d0 +A1 | 0 | no | 47 | no | Codetext | AllplanAttributes - Ortscode_Geschoßbezeichnung: E02; ash_W_Trockenbau_Qualitäten: 8; Sicherheitsklasse: -
 | H2 Ebene +2 | Installationsraum | 1213Wa 0813239243 | yes | Codetext | m² | Trockenbauarbeiten | Wand | Innenwand 1-Schalig | Installationsraum | 0 | A | 7.5 | 1213HWa0812968187 | NEW | no | no | 0 | 0 | no | 47 | no | Codetext | AllplanAttributes - Ortscode_Geschoßbezeichnung: E02; Sicherheitsklasse: -
 | H2 Ebene +2 | WI-HW 60 | 1213Wa 0813239242 | yes | Codetext | m² | Zimmer- und Holzbauarbeiten | Wand | Innenwand 1-Schalig | WI-HW 60 | 0 | A | 7.5 | 1213HWa0812968187 | NEW | no | no | REI 30-A1 - D,s2-d0 +A1 | 0 | no | 47 | no | Codetext | AllplanAttributes - Ortscode_Geschoßbezeichnung: E02; Sicherheitsklasse: -; ash W_laufende Nr. Statik: 3 (W 3.0)
 | H2 Ebene +2 | WI-LB | 1213Wa 0812985956 | yes | Codetext | m² | Trockenbauarbeiten | Wand | Innenwand 1-Schalig | WI-LB | 0 | A | 7.5 | 1213HWa0812968187 | NEW | no | no | REI 30-A1 - D,s2-d0 +A1 | 0 | no | 47 | no | Codetext | AllplanAttributes - Ortscode_Geschoßbezeichnung: E02; ash_W_Trockenbau_Qualitäten: 8; Sicherheitsklasse: -
 | H2 Ebene +2 | Installationsraum | 1213Wa 0813079805 | yes | Codetext | m² | Trockenbauarbeiten | Wand | Innenwand 1-Schalig | Installationsraum | 0 | A | 7.5 | 1213HWa0812968187 | NEW | no | no | 0 | 0 | no | 47 | no | Codetext | AllplanAttributes - Ortscode_Geschoßbezeichnung: E02; Sicherheitsklasse: -
 | H2 Ebene +2 | WI-HW 60 | 1213Wa 0813079806 | yes | Codetext | m² | Zimmer- und Holzbauarbeiten | Wand | Innenwand 1-Schalig | WI-HW 60 | 0 | A | 7.5 | 1213HWa0812968187 | NEW | no | no | REI 30-A1 - D,s2-d0 +A1 | 0 | no | 47 | no | Codetext | AllplanAttributes - Ortscode_Geschoßbezeichnung: E02; Sicherheitsklasse: -; ash W_laufende Nr. Statik: 3 (W 3.0)
 | H2 Ebene +2 | WI-LB | 1213Wa 0812986131 | yes | Codetext | m² | Trockenbauarbeiten | Wand | Innenwand 1-Schalig | WI-LB | 0 | A | 7.5 | 1213HWa0812968289 | NEW | no | no | REI 60-A1 - D,s2-d0 /A1 | 0 | no | 52 | no | Codetext | AllplanAttributes - Ortscode_Geschoßbezeichnung: E02; ash_W_Trockenbau_Qualitäten: 6; Sicherheitsklasse: -
 | H2 Ebene +2 | Installationsraum | 1213Wa 0813084562 | yes | Codetext | m² | Trockenbauarbeiten | Wand | Innenwand 1-Schalig | Installationsraum | 0 | A | 7.5 | 1213HWa0812968289 | NEW | no | no | 0 | 0 | no | 0 | no | Codetext | AllplanAttributes - Ortscode_Geschoßbezeichnung: E02; Sicherheitsklasse: -
 | H2 Ebene +2 | WI-HW 60 | 1213Wa 0813096617 | yes | Codetext | m² | Zimmer- und Holzbauarbeiten | Wand | Innenwand 1-Schalig | WI-HW 60 | 0 | A | 7.5 | 1213HWa0812968289 | NEW | no | no | REI 60-A1 - D,s2-d0 +A1 | 0 | no | 52 | no | Codetext | AllplanAttributes - Ortscode_Geschoßbezeichnung: E02; Sicherheitsklasse: -; ash W_laufende Nr. Statik: 3 (W 3.0)
 | H2 Ebene +2 | WI-LB | 1213Wa 0812986420 | yes | Codetext | m² | Trockenbauarbeiten | Wand | Innenwand 1-Schalig | WI-LB | 0 | A | 7.5 | 1213HWa0812968141 | NEW | no | no | REI 30-A1 - D,s2-d0 +A1 | 0 | no | 0 | no | Codetext | AllplanAttributes - Ortscode_Geschoßbezeichnung: E02; ash_W_Trockenbau_Qualitäten: 16
 | H2 Ebene +2 | WI-HW 60 | 1213Wa 0813196247 | yes | Codetext | m² | Zimmer- und Holzbauarbeiten | Wand | Innenwand 1-Schalig | WI-HW 60 | 0 | A | 7.5 | 1213HWa0812968141 | NEW | yes | no | REI 30-A1 - D,s2-d0 +A1 | 0 | no | 0 | no | Codetext | AllplanAttributes - Ortscode_Geschoßbezeichnung: E02; ash W_laufende Nr. Statik: 1 (W 1.0/ 1.1/ 1.2)
 | H2 Ebene +2 | WI-LB | 1213Wa 0812985983 | yes | Codetext | m² | Trockenbauarbeiten | Wand | Innenwand 1-Schalig | WI-LB | 0 | A | 7.5 | 1213HWa0812968190 | NEW | no | no | REI 60-A1 - D,s2-d0 /A1 | 0 | no | 0 | no | Codetext | AllplanAttributes - Ortscode_Geschoßbezeichnung: E02; ash_W_Trockenbau_Qualitäten: 16
 | H2 Ebene +2 | WI-HW 60 | 1213Wa 0813197001 | yes | Codetext | m² | Zimmer- und Holzbauarbeiten | Wand | Innenwand 1-Schalig | WI-HW 60 | 0 | A | 7.5 | 1213HWa0812968190 | NEW | no | no | REI 60-A1 - D,s2-d0 /A1 | 0 | no | 0 | no | Codetext | AllplanAttributes - Ortscode_Geschoßbezeichnung: E02; ash W_laufende Nr. Statik: 3 (W 3.0)
 | H2 Ebene +2 | WI-LB | 1213Wa 0812970572 | yes | Codetext | m² | Trockenbauarbeiten | Wand | Innenwand 1-Schalig | WI-LB | 0 | A | 7.5 | 1213HWa0812968364 | NEW | no | no | REI 60-A1 - D,s2-d0 /A1 | 0 | no | 47 | no | Codetext | AllplanAttributes - Ortscode_Geschoßbezeichnung: E02; ash_W_Trockenbau_Qualitäten: 6; Sicherheitsklasse: -
 | H2 Ebene +2 | WI-HW 60 | 1213Wa 0813084472 | yes | Codetext | m² | Zimmer- und Holzbauarbeiten | Wand | Innenwand 1-Schalig | WI-HW 60 | 0 | A | 7.5 | 1213HWa0812968364 | NEW | no | no | REI 60-A1 - D,s2-d0 +A1 | 0 | no | 47 | no | Codetext | AllplanAttributes - Ortscode_Geschoßbezeichnung: E02; Sicherheitsklasse: -; ash W_laufende Nr. Statik: 3 (W 3.0)
 | H2 Ebene +2 | WI-LB | 1213Wa 0813410329 | yes | Codetext | m² | Trockenbauarbeiten | Wand | Innenwand 1-Schalig | WI-LB | 0 | A | 7.5 | 1213HWa0812968177 | NEW | no | no | REI 60-A1 - D,s2-d0 /A1 | 0 | no | 52 | no | Codetext | AllplanAttributes - Ortscode_Geschoßbezeichnung: E02; ash_W_Trockenbau_Qualitäten: 6; Sicherheitsklasse: -
 | H2 Ebene +2 | WI-HW 60 | 1213Wa 0813410327 | yes | Codetext | m² | Zimmer- und Holzbauarbeiten | Wand | Innenwand 1-Schalig | WI-HW 60 | 0 | A | 7.5 | 1213HWa0812968177 | NEW | no | no | REI 60-A1 - D,s2-d0 +A1 | 0 | no | 52 | no | Codetext | AllplanAttributes - Ortscode_Geschoßbezeichnung: E02; Sicherheitsklasse: -; ash W_laufende Nr. Statik: 3 (W 3.0)
 | H2 Ebene +2 | WI-HW 60 | 1213Wa 0813637677 | yes | Codetext | m² | Zimmer- und Holzbauarbeiten | Wand | Innenwand 1-Schalig | WI-HW 60 | 0 | A | 7.5 | 1213HWa0812968238 | NEW | no | no | REI 30 | 0 | no | 47 | no | Codetext | AllplanAttributes - Ortscode_Geschoßbezeichnung: E02; Sicherheitsklasse: -; ash W_laufende Nr. Statik: 1 (W 1.0/ 1.1/ 1.2)
 | H2 Ebene +2 | WI-HW 60 | 1213Wa 0813637688 | yes | Codetext | m² | Zimmer- und Holzbauarbeiten | Wand | Innenwand 1-Schalig | WI-HW 60 | 0 | A | 7.5 | 1213HWa0812968238 | NEW | no | no | REI 30 | 0 | no | 47 | no | Codetext | AllplanAttributes - Ortscode_Geschoßbezeichnung: E02; Sicherheitsklasse: -; ash W_laufende Nr. Statik: 1 (W 1.0/ 1.1/ 1.2)
 | H2 Ebene +2 | WI-HW 60 | 1213Wa 0813637699 | yes | Codetext | m² | Zimmer- und Holzbauarbeiten | Wand | Innenwand 1-Schalig | WI-HW 60 | 0 | A | 7.5 | 1213HWa0812968238 | NEW | no | no | REI 30 | 0 | no | 47 | no | Codetext | AllplanAttributes - Ortscode_Geschoßbezeichnung: E02; Sicherheitsklasse: -; ash W_laufende Nr. Statik: 1 (W 1.0/ 1.1/ 1.2)
 | H2 Ebene +2 | WI-HW 60 | 1213Wa 0813637707 | yes | Codetext | m² | Zimmer- und Holzbauarbeiten | Wand | Innenwand 1-Schalig | WI-HW 60 | 0 | A | 7.5 | 1213HWa0812968238 | NEW | no | no | REI 30 | 0 | no | 47 | no | Codetext | AllplanAttributes - Ortscode_Geschoßbezeichnung: E02; Sicherheitsklasse: -; ash W_laufende Nr. Statik: 1 (W 1.0/ 1.1/ 1.2)
 | H2 Ebene +2 | WI-HW 60 | 1213Wa 0813637718 | yes | Codetext | m² | Zimmer- und Holzbauarbeiten | Wand | Innenwand 1-Schalig | WI-HW 60 | 0 | A | 7.5 | 1213HWa0812968238 | NEW | no | no | REI 30 | 0 | no | 47 | no | Codetext | AllplanAttributes - Ortscode_Geschoßbezeichnung: E02; Sicherheitsklasse: -; ash W_laufende Nr. Statik: 1 (W 1.0/ 1.1/ 1.2)
 | H2 Ebene +2 | WI-HW 60 | 1213Wa 0813637729 | yes | Codetext | m² | Zimmer- und Holzbauarbeiten | Wand | Innenwand 1-Schalig | WI-HW 60 | 0 | A | 7.5 | 1213HWa0812968238 | NEW | no | no | REI 30 | 0 | no | 47 | no | Codetext | AllplanAttributes - Ortscode_Geschoßbezeichnung: E02; Sicherheitsklasse: -; ash W_laufende Nr. Statik: 1 (W 1.0/ 1.1/ 1.2)
 | H2 Ebene +2 | WI-HW 60 | 1213Wa 0813637740 | yes | Codetext | m² | Zimmer- und Holzbauarbeiten | Wand | Innenwand 1-Schalig | WI-HW 60 | 0 | A | 7.5 | 1213HWa0812968238 | NEW | no | no | REI 30 | 0 | no | 47 | no | Codetext | AllplanAttributes - Ortscode_Geschoßbezeichnung: E02; Sicherheitsklasse: -; ash W_laufende Nr. Statik: 1 (W 1.0/ 1.1/ 1.2)
 | H2 Ebene +2 | WI-HW 60 | 1213Wa 0813637751 | yes | Codetext | m² | Zimmer- und Holzbauarbeiten | Wand | Innenwand 1-Schalig | WI-HW 60 | 0 | A | 7.5 | 1213HWa0812968238 | NEW | no | no | REI 30 | 0 | no | 47 | no | Codetext | AllplanAttributes - Ortscode_Geschoßbezeichnung: E02; Sicherheitsklasse: -; ash W_laufende Nr. Statik: 1 (W 1.0/ 1.1/ 1.2)
 | H2 Ebene +2 | WI-HW 60 | 1213Wa 0813637762 | yes | Codetext | m² | Zimmer- und Holzbauarbeiten | Wand | Innenwand 1-Schalig | WI-HW 60 | 0 | A | 7.5 | 1213HWa0812968238 | NEW | no | no | REI 30 | 0 | no | 47 | no | Codetext | AllplanAttributes - Ortscode_Geschoßbezeichnung: E02; Sicherheitsklasse: -; ash W_laufende Nr. Statik: 1 (W 1.0/ 1.1/ 1.2)
 | H2 Ebene +2 | WI-HW 60 | 1213Wa 0813637773 | yes | Codetext | m² | Zimmer- und Holzbauarbeiten | Wand | Innenwand 1-Schalig | WI-HW 60 | 0 | A | 7.5 | 1213HWa0812968238 | NEW | no | no | REI 30 | 0 | no | 47 | no | Codetext | AllplanAttributes - Ortscode_Geschoßbezeichnung: E02; Sicherheitsklasse: -; ash W_laufende Nr. Statik: 1 (W 1.0/ 1.1/ 1.2)
 | H2 Ebene +2 | WI-HW 60 | 1213Wa 0813637784 | yes | Codetext | m² | Zimmer- und Holzbauarbeiten | Wand | Innenwand 1-Schalig | WI-HW 60 | 0 | A | 7.5 | 1213HWa0812968238 | NEW | no | no | REI 30 | 0 | no | 47 | no | Codetext | AllplanAttributes - Ortscode_Geschoßbezeichnung: E02; Sicherheitsklasse: -; ash W_laufende Nr. Statik: 1 (W 1.0/ 1.1/ 1.2)
 | H2 Ebene +2 | WI-HW 60 | 1213Wa 0813637795 | yes | Codetext | m² | Zimmer- und Holzbauarbeiten | Wand | Innenwand 1-Schalig | WI-HW 60 | 0 | A | 7.5 | 1213HWa0812968238 | NEW | no | no | REI 30 | 0 | no | 47 | no | Codetext | AllplanAttributes - Ortscode_Geschoßbezeichnung: E02; Sicherheitsklasse: -; ash W_laufende Nr. Statik: 1 (W 1.0/ 1.1/ 1.2)
 | H2 Ebene +2 | WI-LB | 1213Wa 0812970624 |  | Codetext | m² | Trockenbauarbeiten | Wand |  |  | 0 | A | 7.5 | 1213HWa0812968243 | NEW | no | no | 0 | 0 | no | 0 | no | Codetext | AllplanAttributes - Ortscode_Geschoßbezeichnung: E02; W_Deckenanschluss: Gleitender Deckenanschluss Fall 03; ash_W_Trockenbau_Qualitäten: 10a
 | H2 Ebene +2 | WI-LB | 1213Wa 0812970619 |  | Codetext | m² | Trockenbauarbeiten | Wand |  |  | 0 | A | 7.5 | 1213HWa0812968245 | NEW | no | no | 0 | 0 | no | 0 | no | Codetext | AllplanAttributes - Ortscode_Geschoßbezeichnung: E02; W_Deckenanschluss: Gleitender Deckenanschluss Fall 03; ash_W_Trockenbau_Qualitäten: 10a
 | H2 Ebene +2 | WI-LB | 1213Wa 0812970639 | yes | Codetext | m² | Trockenbauarbeiten | Wand | Innenwand 1-Schalig | WI-LB | 0 | A | 7.5 | 1213HWa0812968264 | NEW | no | no | 0 | 0 | no | 0 | no | Codetext | AllplanAttributes - Ortscode_Geschoßbezeichnung: E02; W_Deckenanschluss: Gleitender Deckenanschluss Fall 03; ash_W_Trockenbau_Qualitäten: 1b
 | H2 Ebene +2 | WI-LB | 1213Wa 0812970637 | yes | Codetext | m² | Trockenbauarbeiten | Wand | Innenwand 1-Schalig | WI-LB | 0 | A | 7.5 | 1213HWa0812968263 | NEW | no | no | 0 | 0 | no | 0 | no | Codetext | AllplanAttributes - Ortscode_Geschoßbezeichnung: E02; W_Deckenanschluss: Gleitender Deckenanschluss Fall 03; ash_W_Trockenbau_Qualitäten: 1b
 | H2 Ebene +2 | WI-LB | 1213Wa 0813019383 | yes | Codetext | m² | Trockenbauarbeiten | Wand | Innenwand 1-Schalig | WI-LB | 0 | A | 7.5 | 1213HWa0813019381 | NEW | no | no | 0 | 0 | no | 0 | no | Codetext | AllplanAttributes - Ortscode_Geschoßbezeichnung: E02; W_Deckenanschluss: Gleitender Deckenanschluss Fall 03; ash_W_Trockenbau_Qualitäten: 1b
 | H2 Ebene +2 | WI-LB | 1213Wa 0812970632 | yes | Codetext | m² | Trockenbauarbeiten | Wand | Innenwand 1-Schalig | WI-LB | 0 | A | 7.5 | 1213HWa0812968262 | NEW | no | no | 0 | 0 | no | 0 | no | Codetext | AllplanAttributes - Ortscode_Geschoßbezeichnung: E02; W_Deckenanschluss: Gleitender Deckenanschluss Fall 03; ash_W_Trockenbau_Qualitäten: 1b
 | H2 Ebene +2 | WI-LB | 1213Wa 0812970968 |  | Codetext | m² | Trockenbauarbeiten | Wand |  |  | 0 | A | 7.5 | 1213HWa0812968258 | NEW | no | no | 0 | 0 | no | 0 | no | Codetext | AllplanAttributes - Ortscode_Geschoßbezeichnung: E02; W_Deckenanschluss: Gleitender Deckenanschluss Fall 03; ash_W_Trockenbau_Qualitäten: 10a
 | H2 Ebene +2 | WI-IW | 1213Wa 0812970814 | yes | Codetext | m² | Trockenbauarbeiten | Wand | Installationswand | WI-IW | 0 | A | 7.5 | 1213HWa0812968248 | NEW | no | no | 0 | 0 | no | 0 | no | Codetext | AllplanAttributes - Ortscode_Geschoßbezeichnung: E02; W_Deckenanschluss: Gleitender Deckenanschluss Fall 03; ash_W_Trockenbau_Qualitäten: 2
 | H2 Ebene +2 | Installationsraum | 1213Wa 0812970834 | yes | Codetext | m² | Trockenbauarbeiten | Wand | Installationswand | Installationsraum | 0 | A | 7.5 | 1213HWa0812968248 | NEW | no | no | 0 | 0 | no | 0 | no | Codetext | AllplanAttributes - Ortscode_Geschoßbezeichnung: E02
 | H2 Ebene +2 | WI-IW | 1213Wa 0812970810 | yes | Codetext | m² | Trockenbauarbeiten | Wand | Installationswand | WI-IW | 0 | A | 7.5 | 1213HWa0812968248 | NEW | no | no | 0 | 0 | no | 0 | no | Codetext | AllplanAttributes - Ortscode_Geschoßbezeichnung: E02; W_Deckenanschluss: Gleitender Deckenanschluss Fall 03; ash_W_Trockenbau_Qualitäten: 2
 | H2 Ebene +2 | Installationsraum | 1213Wa 0812970838 | yes | Codetext | m² | Trockenbauarbeiten | Wand | Installationswand | Installationsraum | 0 | A | 7.5 | 1213HWa0812968248 | NEW | no | no | 0 | 0 | no | 0 | no | Codetext | AllplanAttributes - Ortscode_Geschoßbezeichnung: E02
 | H2 Ebene +2 | WI-IW | 1213Wa 0812970812 | yes | Codetext | m² | Trockenbauarbeiten | Wand | Installationswand | WI-IW | 0 | A | 7.5 | 1213HWa0812968248 | NEW | no | no | 0 | 0 | no | 0 | no | Codetext | AllplanAttributes - Ortscode_Geschoßbezeichnung: E02; W_Deckenanschluss: Gleitender Deckenanschluss Fall 03; ash_W_Trockenbau_Qualitäten: 2
 | H2 Ebene +2 | Installationsraum | 1213Wa 0812970836 | yes | Codetext | m² | Trockenbauarbeiten | Wand | Installationswand | Installationsraum | 0 | A | 7.5 | 1213HWa0812968248 | NEW | no | no | 0 | 0 | no | 0 | no | Codetext | AllplanAttributes - Ortscode_Geschoßbezeichnung: E02
 | H2 Ebene +2 | WI-IW | 1213Wa 0812970824 | yes | Codetext | m² | Trockenbauarbeiten | Wand | Installationswand | WI-IW | 0 | A | 7.5 | 1213HWa0812968250 | NEW | no | no | 0 | 0 | no | 47 | no | Codetext | AllplanAttributes - Ortscode_Geschoßbezeichnung: E02; W_Deckenanschluss: Gleitender Deckenanschluss Fall 03; ash_W_Trockenbau_Qualitäten: 11
 | H2 Ebene +2 | Installationsraum | 1213Wa 0812970826 | yes | Codetext | m² | Trockenbauarbeiten | Wand | Installationswand | Installationsraum | 0 | A | 7.5 | 1213HWa0812968250 | NEW | no | no | 0 | 0 | no | 0 | no | Codetext | AllplanAttributes - Ortscode_Geschoßbezeichnung: E02
 | H2 Ebene +2 | WI-IW | 1213Wa 0812970822 | yes | Codetext | m² | Trockenbauarbeiten | Wand | Installationswand | WI-IW | 0 | A | 7.5 | 1213HWa0812968250 | NEW | no | no | 0 | 0 | no | 47 | no | Codetext | AllplanAttributes - Ortscode_Geschoßbezeichnung: E02; W_Deckenanschluss: Gleitender Deckenanschluss Fall 03; ash_W_Trockenbau_Qualitäten: 11
 | H2 Ebene +2 | WI-IW | 1213Wa 0812970806 | yes | Codetext | m² | Trockenbauarbeiten | Wand | Installationswand | WI-IW | 0 | A | 7.5 | 1213HWa0812968248 | NEW | no | no | 0 | 0 | no | 0 | no | Codetext | AllplanAttributes - Ortscode_Geschoßbezeichnung: E02; W_Deckenanschluss: Gleitender Deckenanschluss Fall 03; ash_W_Trockenbau_Qualitäten: 2
 | H2 Ebene +2 | Installationsraum | 1213Wa 0812970842 | yes | Codetext | m² | Trockenbauarbeiten | Wand | Installationswand | Installationsraum | 0 | A | 7.5 | 1213HWa0812968248 | NEW | no | no | 0 | 0 | no | 0 | no | Codetext | AllplanAttributes - Ortscode_Geschoßbezeichnung: E02
 | H2 Ebene +2 | WI-IW | 1213Wa 0812970816 | yes | Codetext | m² | Trockenbauarbeiten | Wand | Installationswand | WI-IW | 0 | A | 7.5 | 1213HWa0812968250 | NEW | no | no | 0 | 0 | no | 47 | no | Codetext | AllplanAttributes - Ortscode_Geschoßbezeichnung: E02; W_Deckenanschluss: Gleitender Deckenanschluss Fall 03; ash_W_Trockenbau_Qualitäten: 11
 | H2 Ebene +2 | Installationsraum | 1213Wa 0812970820 | yes | Codetext | m² | Trockenbauarbeiten | Wand | Installationswand | Installationsraum | 0 | A | 7.5 | 1213HWa0812968250 | NEW | no | no | 0 | 0 | no | 0 | no | Codetext | AllplanAttributes - Ortscode_Geschoßbezeichnung: E02
 | H2 Ebene +2 | WI-IW | 1213Wa 0812970818 | yes | Codetext | m² | Trockenbauarbeiten | Wand | Installationswand | WI-IW | 0 | A | 7.5 | 1213HWa0812968250 | NEW | no | no | 0 | 0 | no | 47 | no | Codetext | AllplanAttributes - Ortscode_Geschoßbezeichnung: E02; W_Deckenanschluss: Gleitender Deckenanschluss Fall 03; ash_W_Trockenbau_Qualitäten: 11
 | H2 Ebene +2 | WI-IW | 1213Wa 0812970808 | yes | Codetext | m² | Trockenbauarbeiten | Wand | Installationswand | WI-IW | 0 | A | 7.5 | 1213HWa0812968248 | NEW | no | no | 0 | 0 | no | 0 | no | Codetext | AllplanAttributes - Ortscode_Geschoßbezeichnung: E02; W_Deckenanschluss: Gleitender Deckenanschluss Fall 03; ash_W_Trockenbau_Qualitäten: 2
 | H2 Ebene +2 | Installationsraum | 1213Wa 0812970840 | yes | Codetext | m² | Trockenbauarbeiten | Wand | Installationswand | Installationsraum | 0 | A | 7.5 | 1213HWa0812968248 | NEW | no | no | 0 | 0 | no | 0 | no | Codetext | AllplanAttributes - Ortscode_Geschoßbezeichnung: E02
 | H2 Ebene +2 | WI-IW | 1213Wa 0812970846 | yes | Codetext | m² | Trockenbauarbeiten | Wand | Installationswand | WI-IW | 0 | A | 7.5 | 1213HWa0812968248 | NEW | no | no | 0 | 0 | no | 0 | no | Codetext | AllplanAttributes - Ortscode_Geschoßbezeichnung: E02; W_Deckenanschluss: Gleitender Deckenanschluss Fall 03; ash_W_Trockenbau_Qualitäten: 2
 | H2 Ebene +2 | Installationsraum | 1213Wa 0812970804 | yes | Codetext | m² | Trockenbauarbeiten | Wand | Installationswand | Installationsraum | 0 | A | 7.5 | 1213HWa0812968248 | NEW | no | no | 0 | 0 | no | 0 | no | Codetext | AllplanAttributes - Ortscode_Geschoßbezeichnung: E02
 | H2 Ebene +2 | WI-IW | 1213Wa 0812970844 | yes | Codetext | m² | Trockenbauarbeiten | Wand | Installationswand | WI-IW | 0 | A | 7.5 | 1213HWa0812968260 | NEW | no | no | 0 | 0 | no | 0 | no | Codetext | AllplanAttributes - Ortscode_Geschoßbezeichnung: E02; W_Deckenanschluss: Gleitender Deckenanschluss Fall 03; ash_W_Trockenbau_Qualitäten: 2
 | H2 Ebene +2 | Installationsraum | 1213Wa 0812970970 | yes | Codetext | m² | Trockenbauarbeiten | Wand | Installationswand | Installationsraum | 0 | A | 7.5 | 1213HWa0812968260 | NEW | no | no | 0 | 0 | no | 0 | no | Codetext | AllplanAttributes - Ortscode_Geschoßbezeichnung: E02
 | H2 Ebene +2 | WI-VS | 1213Wa 0812970541 | yes | Codetext | m² | Trockenbauarbeiten | Wand | Innenwand 1-Schalig | WI-VS | 0 | A | 7.5 | 1213HWa0812968098 | NEW | no | no | 0 | 0 | no |  | no | Codetext | AllplanAttributes - Ortscode_Geschoßbezeichnung: E02; W_Deckenanschluss: Gleitender Deckenanschluss Fall 01; ash_W_Trockenbau_Qualitäten: 11
 | H2 Ebene +2 | Installationsraum | 1213Wa 0813641186 | yes | Codetext | m² | Trockenbauarbeiten | Wand | Innenwand 1-Schalig | Installationsraum | 0 | A | 7.5 | 1213HWa0812968098 | NEW | no | no | 0 | 0 | no | 0 | no | Codetext | AllplanAttributes - Ortscode_Geschoßbezeichnung: E02
 | H2 Ebene +2 | WI-LB | 1213Wa 0813641187 | yes | Codetext | m² | Trockenbauarbeiten | Wand | Innenwand 1-Schalig | WI-LB | 0 | A | 7.5 | 1213HWa0812968198 | NEW | no | no | REI 30-A1 - D,s2-d0 +A1 | 0 | no |  | no | Codetext | AllplanAttributes - Ortscode_Geschoßbezeichnung: E02; W_Deckenanschluss: Gleitender Deckenanschluss Fall 01; ash_W_Trockenbau_Qualitäten: 11
 | H2 Ebene +2 | WI-IW | 1213Wa 0812986184 | yes | Codetext | m² | Trockenbauarbeiten | Wand | Innenwand 1-Schalig | WI-IW | 0 | A | 7.5 | 1213HWa0812968136 | NEW | no | no | REI 30-A1 - D,s2-d0 +A1 | 0 | no | 0 | no | Codetext | AllplanAttributes - Ortscode_Geschoßbezeichnung: E02; ash_W_Trockenbau_Qualitäten: 16
 | H2 Ebene +2 | WI-HW 60 | 1213Wa 0813092550 | yes | Codetext | m² | Zimmer- und Holzbauarbeiten | Wand | Innenwand 1-Schalig | WI-HW 60 | 0 | A | 7.5 | 1213HWa0812968136 | NEW | no | no | REI 30-A1 - D,s2-d0 +A1 | 0 | no | 0 | no | Codetext | AllplanAttributes - Ortscode_Geschoßbezeichnung: E02; ash W_laufende Nr. Statik: 3 (W 3.0)
 | H2 Ebene +2 | WI-IW | 1213Wa 0813641467 | yes | Codetext | m² | Trockenbauarbeiten | Wand | Innenwand 1-Schalig | WI-IW | 0 | A | 7.5 | 1213HWa0812968136 | NEW | no | no | REI 30-A1 - D,s2-d0 +A1 | 0 | no | 0 | no | Codetext | AllplanAttributes - Ortscode_Geschoßbezeichnung: E02; ash_W_Trockenbau_Qualitäten: 16
 | H2 Ebene +2 | WI-HW 60 | 1213Wa 0813641465 | yes | Codetext | m² | Zimmer- und Holzbauarbeiten | Wand | Innenwand 1-Schalig | WI-HW 60 | 0 | A | 7.5 | 1213HWa0812968136 | NEW | no | no | REI 30-A1 - D,s2-d0 +A1 | 0 | no | 0 | no | Codetext | AllplanAttributes - Ortscode_Geschoßbezeichnung: E02; ash W_laufende Nr. Statik: 3 (W 3.0)
 | H2 Ebene +2 | WI-LB | 1213Wa 0812970547 | yes | Codetext | m² | Trockenbauarbeiten | Wand | Innenwand 1-Schalig | WI-LB | 0 | A | 7.5 | 1213HWa0812968097 | NEW | no | no | REI 60-A1 - D,s2-d0 +A1 | 0 | no |  | no | Codetext | AllplanAttributes - Ortscode_Geschoßbezeichnung: E02; W_Deckenanschluss: Gleitender Deckenanschluss Fall 01; ash_W_Trockenbau_Qualitäten: 1b
 | H2 Ebene +2 | Installationsraum | 1213Wa 0812970543 | yes | Codetext | m² | Trockenbauarbeiten | Wand | Installationswand | Installationsraum | 0 | A | 7.5 | 1213HWa0812968197 | NEW | no | no | 0 | 0 | no | 0 | no | Codetext | AllplanAttributes - Ortscode_Geschoßbezeichnung: E02
 | H2 Ebene +2 | WI-VS | 1213Wa 0812970545 | yes | Codetext | m² | Trockenbauarbeiten | Wand | Installationswand | WI-VS | 0 | A | 7.5 | 1213HWa0812968197 | NEW | no | no | 0 | 0 | no | 0 | no | Codetext | AllplanAttributes - Ortscode_Geschoßbezeichnung: E02; W_Deckenanschluss: Gleitender Deckenanschluss Fall 01; ash_W_Trockenbau_Qualitäten: 2
 | H2 Ebene +2 | WI-STB | 1213Wa 0813567176 | yes |  | m² | Zimmer- und Holzbauarbeiten | Wand | Innenwand 1-Schalig | WI-STB |  |  | 7.5 |  | NEW | no |  | 0 |  |  | 0 | AllplanAttributes - Ortscode_Geschoßbezeichnung: E02; Sicherheitsklasse: -
 | H2 Ebene +2 | WI-STB | 1213Wa 0813567177 | yes |  | m² | Zimmer- und Holzbauarbeiten | Wand | Innenwand 1-Schalig | WI-STB |  |  | 7.5 |  | NEW | no |  | 0 |  |  | 0 | AllplanAttributes - Ortscode_Geschoßbezeichnung: E02; Sicherheitsklasse: -
 | H2 Ebene +2 | WI-LB | 1213Wa 0813567178 | yes |  | m² | Trockenbauarbeiten | Wand | Innenwand 1-Schalig | WI-LB |  |  | 7.5 |  | NEW | no |  | 0 |  |  | 0 | AllplanAttributes - Ortscode_Geschoßbezeichnung: E02; ash_W_Trockenbau_Qualitäten: 9; Sicherheitsklasse: -
 | H2 Ebene +2 | WI-HW 60 | 1213Wa 0812970942 | yes | Codetext | m² | Zimmer- und Holzbauarbeiten | Wand | Innenwand 1-Schalig | WI-HW 60 | 0 | A | 7.5 | 1213HWa0812968124 | NEW |  | no | 0 | 0 | no | 47 | no | Codetext | AllplanAttributes - Ortscode_Geschoßbezeichnung: E02; Sicherheitsklasse: -; ash W_laufende Nr. Statik: 3 (W 3.0)
 | H2 Ebene +2 | WI-LB | 1213Wa 0813092484 | yes | Codetext | m² | Trockenbauarbeiten | Wand | Innenwand 1-Schalig | WI-LB | 0 | A | 7.5 | 1213HWa0812968124 | NEW |  | no | 0 | 0 | no | 47 | no | Codetext | AllplanAttributes - Ortscode_Geschoßbezeichnung: E02; ash_W_Trockenbau_Qualitäten: 6; Sicherheitsklasse: -
 | H2 Ebene +2 | WI-LB | 1213Wa 0813643245 | yes | Codetext | m² | Trockenbauarbeiten | Wand | Innenwand 1-Schalig | WI-LB | 0 | A | 7.5 | 1213HWa0812968123 | NEW | no | no | REI 30-A1 - D,s2-d0 +A1 | 0 | no | 47 | no | Codetext | AllplanAttributes - Ortscode_Geschoßbezeichnung: E02; ash_W_Trockenbau_Qualitäten: 8; Sicherheitsklasse: -
 | H2 Ebene +2 | Installationsraum | 1213Wa 0813643248 | yes | Codetext | m² | Trockenbauarbeiten | Wand | Innenwand 1-Schalig | Installationsraum | 0 | A | 7.5 | 1213HWa0812968123 | NEW | no | no | 0 | 0 | no | 47 | no | Codetext | AllplanAttributes - Ortscode_Geschoßbezeichnung: E02; Sicherheitsklasse: -
 | H2 Ebene +2 | WI-HW 60 | 1213Wa 0813643249 | yes | Codetext | m² | Zimmer- und Holzbauarbeiten | Wand | Innenwand 1-Schalig | WI-HW 60 | 0 | A | 7.5 | 1213HWa0812968123 | NEW | no | no | REI 30-A1 - D,s2-d0 +A1 | 0 | no | 47 | no | Codetext | AllplanAttributes - Ortscode_Geschoßbezeichnung: E02; Sicherheitsklasse: -; ash W_laufende Nr. Statik: 3 (W 3.0)
 | H2 Ebene +2 | WI-HW 60 | 1213Wa 0813643345 | yes | Codetext | m² | Zimmer- und Holzbauarbeiten | Wand | Innenwand 1-Schalig | WI-HW 60 | 0 | A | 7.5 | 1213HWa0812968123 | NEW | no | no | REI 30-A1 - D,s2-d0 +A1 | 0 | no | 47 | no | Codetext | AllplanAttributes - Ortscode_Geschoßbezeichnung: E02; Sicherheitsklasse: -; ash W_laufende Nr. Statik: 3 (W 3.0)
 | H2 Ebene +2 | WI-LB | 1213Wa 0813642533 | yes | Codetext | m² | Trockenbauarbeiten | Wand | Innenwand 1-Schalig | WI-LB | 0 | A | 7.5 | 1213HWa0812968123 | NEW | no | no | REI 30-A1 - D,s2-d0 +A1 | 0 | no | 47 | no | Codetext | AllplanAttributes - Ortscode_Geschoßbezeichnung: E02; ash_W_Trockenbau_Qualitäten: 8; Sicherheitsklasse: -
 | H2 Ebene +2 | Installationsraum | 1213Wa 0813642536 | yes | Codetext | m² | Trockenbauarbeiten | Wand | Innenwand 1-Schalig | Installationsraum | 0 | A | 7.5 | 1213HWa0812968123 | NEW | no | no | 0 | 0 | no | 47 | no | Codetext | AllplanAttributes - Ortscode_Geschoßbezeichnung: E02; Sicherheitsklasse: -
 | H2 Ebene +2 | WI-HW 60 | 1213Wa 0813642504 | yes | Codetext | m² | Zimmer- und Holzbauarbeiten | Wand | Innenwand 1-Schalig | WI-HW 60 | 0 | A | 7.5 | 1213HWa0812968123 | NEW | no | no | REI 30-A1 - D,s2-d0 +A1 | 0 | no | 47 | no | Codetext | AllplanAttributes - Ortscode_Geschoßbezeichnung: E02; Sicherheitsklasse: -; ash W_laufende Nr. Statik: 3 (W 3.0)
 | H2 Ebene +2 | WI-LB | 1213Wa 0813643701 | yes | Codetext | m² | Trockenbauarbeiten | Wand | Innenwand 1-Schalig | WI-LB | 0 | A | 7.5 | 1213HWa0812968123 | NEW | no | no | REI 30-A1 - D,s2-d0 +A1 | 0 | no | 47 | no | Codetext | AllplanAttributes - Ortscode_Geschoßbezeichnung: E02; ash_W_Trockenbau_Qualitäten: 8; Sicherheitsklasse: -
 | H2 Ebene +2 | Installationsraum | 1213Wa 0813643700 | yes | Codetext | m² | Trockenbauarbeiten | Wand | Innenwand 1-Schalig | Installationsraum | 0 | A | 7.5 | 1213HWa0812968123 | NEW | no | no | 0 | 0 | no | 47 | no | Codetext | AllplanAttributes - Ortscode_Geschoßbezeichnung: E02; Sicherheitsklasse: -
 | H2 Ebene +2 | WI-HW 60 | 1213Wa 0813643704 | yes | Codetext | m² | Zimmer- und Holzbauarbeiten | Wand | Innenwand 1-Schalig | WI-HW 60 | 0 | A | 7.5 | 1213HWa0812968123 | NEW | no | no | REI 30-A1 - D,s2-d0 +A1 | 0 | no | 47 | no | Codetext | AllplanAttributes - Ortscode_Geschoßbezeichnung: E02; Sicherheitsklasse: -; ash W_laufende Nr. Statik: 3 (W 3.0)
 | H2 Ebene +2 | WI-HW 60 | 1213Wa 0813643764 | yes | Codetext | m² | Zimmer- und Holzbauarbeiten | Wand | Innenwand 1-Schalig | WI-HW 60 | 0 | A | 7.5 | 1213HWa0812968123 | NEW | no | no | REI 30-A1 - D,s2-d0 +A1 | 0 | no | 47 | no | Codetext | AllplanAttributes - Ortscode_Geschoßbezeichnung: E02; Sicherheitsklasse: -; ash W_laufende Nr. Statik: 3 (W 3.0)
 | H2 Ebene +2 | WI-IW | 1213Wa 0813026333 | yes | Codetext | m² | Trockenbauarbeiten | Wand | Installationswand | WI-IW | 0 | A | 7.5 | 1213HWa0813026332 | NEW |  | no | 0 | 0 | no | 47 | no | Codetext | AllplanAttributes - Ortscode_Geschoßbezeichnung: E02; W_Deckenanschluss: Gleitender Deckenanschluss Fall 01; ash_W_Trockenbau_Qualitäten: 19
 | H2 Ebene +2 | WI-HW 60 | 1213Wa 0812970927 | yes | Codetext | m² | Zimmer- und Holzbauarbeiten | Wand | Innenwand 1-Schalig | WI-HW 60 | 0 | A | 7.5 | 1213HWa0812968122 | NEW |  | no | 0 | 0 | no | 47 | no | Codetext | AllplanAttributes - Ortscode_Geschoßbezeichnung: E02; Sicherheitsklasse: -; ash W_laufende Nr. Statik: 3 (W 3.0)
 | H2 Ebene +2 | WI-LB | 1213Wa 0813092450 | yes | Codetext | m² | Trockenbauarbeiten | Wand | Innenwand 1-Schalig | WI-LB | 0 | A | 7.5 | 1213HWa0812968122 | NEW |  | no | 0 | 0 | no | 47 | no | Codetext | AllplanAttributes - Ortscode_Geschoßbezeichnung: E02; ash_W_Trockenbau_Qualitäten: 6; Sicherheitsklasse: -
 | H2 Ebene +2 | WI-LB | 1213Wa 0813644047 | yes | Codetext | m² | Trockenbauarbeiten | Wand | Innenwand 1-Schalig | WI-LB | 0 | A | 7.5 | 1213HWa0812968205 | NEW |  | no | REI 30-A1 - D,s2-d0 +A1 | 0 | no | 47 | no | Codetext | AllplanAttributes - Ortscode_Geschoßbezeichnung: E02; W_Deckenanschluss: Gleitender Deckenanschluss Fall 01; ash_W_Trockenbau_Qualitäten: 1b
 | H2 Ebene +2 | WI-LB | 1213Wa 0813644059 | yes | Codetext | m² | Trockenbauarbeiten | Wand | Innenwand 1-Schalig | WI-LB | 0 | A | 7.5 | 1213HWa0812968205 | NEW |  | no | REI 30-A1 - D,s2-d0 +A1 | 0 | no | 47 | no | Codetext | AllplanAttributes - Ortscode_Geschoßbezeichnung: E02; W_Deckenanschluss: Gleitender Deckenanschluss Fall 01; ash_W_Trockenbau_Qualitäten: 1b
 | H2 Ebene +2 | WI-LB | 1213Wa 0813644069 | yes | Codetext | m² | Trockenbauarbeiten | Wand | Innenwand 1-Schalig | WI-LB | 0 | A | 7.5 | 1213HWa0812968205 | NEW |  | no | REI 30-A1 - D,s2-d0 +A1 | 0 | no | 47 | no | Codetext | AllplanAttributes - Ortscode_Geschoßbezeichnung: E02; W_Deckenanschluss: Gleitender Deckenanschluss Fall 01; ash_W_Trockenbau_Qualitäten: 1b
 | H2 Ebene +2 | WI-IW | 1213Wa 0812970858 | yes | Codetext | m² | Trockenbauarbeiten | Wand | Installationswand | WI-IW | 0 | A | 7.5 | 1213HWa0812968248 | NEW | no | no | 0 | 0 | no | 0 | no | Codetext | AllplanAttributes - Ortscode_Geschoßbezeichnung: E02; W_Deckenanschluss: Gleitender Deckenanschluss Fall 03; ash_W_Trockenbau_Qualitäten: 2
 | H2 Ebene +2 | Installationsraum | 1213Wa 0812970892 | yes | Codetext | m² | Trockenbauarbeiten | Wand | Installationswand | Installationsraum | 0 | A | 7.5 | 1213HWa0812968248 | NEW | no | no | 0 | 0 | no | 0 | no | Codetext | AllplanAttributes - Ortscode_Geschoßbezeichnung: E02
 | H2 Ebene +2 | WI-IW | 1213Wa 0812970900 | yes | Codetext | m² | Trockenbauarbeiten | Wand | Installationswand | WI-IW | 0 | A | 7.5 | 1213HWa0812968250 | NEW | no | no | 0 | 0 | no | 47 | no | Codetext | AllplanAttributes - Ortscode_Geschoßbezeichnung: E02; W_Deckenanschluss: Gleitender Deckenanschluss Fall 03; ash_W_Trockenbau_Qualitäten: 11
 | H2 Ebene +2 | Installationsraum | 1213Wa 0812970896 | yes | Codetext | m² | Trockenbauarbeiten | Wand | Installationswand | Installationsraum | 0 | A | 7.5 | 1213HWa0812968250 | NEW | no | no | 0 | 0 | no | 0 | no | Codetext | AllplanAttributes - Ortscode_Geschoßbezeichnung: E02
 | H2 Ebene +2 | WI-IW | 1213Wa 0812970898 | yes | Codetext | m² | Trockenbauarbeiten | Wand | Installationswand | WI-IW | 0 | A | 7.5 | 1213HWa0812968250 | NEW | no | no | 0 | 0 | no | 47 | no | Codetext | AllplanAttributes - Ortscode_Geschoßbezeichnung: E02; W_Deckenanschluss: Gleitender Deckenanschluss Fall 03; ash_W_Trockenbau_Qualitäten: 11
 | H2 Ebene +2 | WI-IW | 1213Wa 0812970856 | yes | Codetext | m² | Trockenbauarbeiten | Wand | Installationswand | WI-IW | 0 | A | 7.5 | 1213HWa0812968248 | NEW | no | no | 0 | 0 | no | 0 | no | Codetext | AllplanAttributes - Ortscode_Geschoßbezeichnung: E02; W_Deckenanschluss: Gleitender Deckenanschluss Fall 03; ash_W_Trockenbau_Qualitäten: 2
 | H2 Ebene +2 | Installationsraum | 1213Wa 0812970890 | yes | Codetext | m² | Trockenbauarbeiten | Wand | Installationswand | Installationsraum | 0 | A | 7.5 | 1213HWa0812968248 | NEW | no | no | 0 | 0 | no | 0 | no | Codetext | AllplanAttributes - Ortscode_Geschoßbezeichnung: E02
 | H2 Ebene +2 | WI-IW | 1213Wa 0812970852 | yes | Codetext | m² | Trockenbauarbeiten | Wand | Installationswand | WI-IW | 0 | A | 7.5 | 1213HWa0812968248 | NEW | no | no | 0 | 0 | no | 0 | no | Codetext | AllplanAttributes - Ortscode_Geschoßbezeichnung: E02; W_Deckenanschluss: Gleitender Deckenanschluss Fall 03; ash_W_Trockenbau_Qualitäten: 2
 | H2 Ebene +2 | Installationsraum | 1213Wa 0812970886 | yes | Codetext | m² | Trockenbauarbeiten | Wand | Installationswand | Installationsraum | 0 | A | 7.5 | 1213HWa0812968248 | NEW | no | no | 0 | 0 | no | 0 | no | Codetext | AllplanAttributes - Ortscode_Geschoßbezeichnung: E02
 | H2 Ebene +2 | WI-IW | 1213Wa 0812970882 | yes | Codetext | m² | Trockenbauarbeiten | Wand | Installationswand | WI-IW | 0 | A | 7.5 | 1213HWa0812968250 | NEW | no | no | 0 | 0 | no | 47 | no | Codetext | AllplanAttributes - Ortscode_Geschoßbezeichnung: E02; W_Deckenanschluss: Gleitender Deckenanschluss Fall 03; ash_W_Trockenbau_Qualitäten: 11
 | H2 Ebene +2 | Installationsraum | 1213Wa 0812970878 | yes | Codetext | m² | Trockenbauarbeiten | Wand | Installationswand | Installationsraum | 0 | A | 7.5 | 1213HWa0812968250 | NEW | no | no | 0 | 0 | no | 0 | no | Codetext | AllplanAttributes - Ortscode_Geschoßbezeichnung: E02
 | H2 Ebene +2 | WI-IW | 1213Wa 0812970880 | yes | Codetext | m² | Trockenbauarbeiten | Wand | Installationswand | WI-IW | 0 | A | 7.5 | 1213HWa0812968250 | NEW | no | no | 0 | 0 | no | 47 | no | Codetext | AllplanAttributes - Ortscode_Geschoßbezeichnung: E02; W_Deckenanschluss: Gleitender Deckenanschluss Fall 03; ash_W_Trockenbau_Qualitäten: 11
 | H2 Ebene +2 | WI-IW | 1213Wa 0812970854 | yes | Codetext | m² | Trockenbauarbeiten | Wand | Installationswand | WI-IW | 0 | A | 7.5 | 1213HWa0812968248 | NEW | no | no | 0 | 0 | no | 0 | no | Codetext | AllplanAttributes - Ortscode_Geschoßbezeichnung: E02; W_Deckenanschluss: Gleitender Deckenanschluss Fall 03; ash_W_Trockenbau_Qualitäten: 2
 | H2 Ebene +2 | Installationsraum | 1213Wa 0812970888 | yes | Codetext | m² | Trockenbauarbeiten | Wand | Installationswand | Installationsraum | 0 | A | 7.5 | 1213HWa0812968248 | NEW | no | no | 0 | 0 | no | 0 | no | Codetext | AllplanAttributes - Ortscode_Geschoßbezeichnung: E02
 | H2 Ebene +2 | WI-IW | 1213Wa 0812970848 | yes | Codetext | m² | Trockenbauarbeiten | Wand | Installationswand | WI-IW | 0 | A | 7.5 | 1213HWa0812968248 | NEW | no | no | 0 | 0 | no | 0 | no | Codetext | AllplanAttributes - Ortscode_Geschoßbezeichnung: E02; W_Deckenanschluss: Gleitender Deckenanschluss Fall 03; ash_W_Trockenbau_Qualitäten: 2
 | H2 Ebene +2 | Installationsraum | 1213Wa 0812970894 | yes | Codetext | m² | Trockenbauarbeiten | Wand | Installationswand | Installationsraum | 0 | A | 7.5 | 1213HWa0812968248 | NEW | no | no | 0 | 0 | no | 0 | no | Codetext | AllplanAttributes - Ortscode_Geschoßbezeichnung: E02
 | H2 Ebene +2 | WI-IW | 1213Wa 0812970905 | yes | Codetext | m² | Trockenbauarbeiten | Wand | Installationswand | WI-IW | 0 | A | 7.5 | 1213HWa0812968250 | NEW | no | no | 0 | 0 | no | 47 | no | Codetext | AllplanAttributes - Ortscode_Geschoßbezeichnung: E02; W_Deckenanschluss: Gleitender Deckenanschluss Fall 03; ash_W_Trockenbau_Qualitäten: 11
 | H2 Ebene +2 | Installationsraum | 1213Wa 0812970907 | yes | Codetext | m² | Trockenbauarbeiten | Wand | Installationswand | Installationsraum | 0 | A | 7.5 | 1213HWa0812968250 | NEW | no | no | 0 | 0 | no | 0 | no | Codetext | AllplanAttributes - Ortscode_Geschoßbezeichnung: E02
 | H2 Ebene +2 | WI-IW | 1213Wa 0812970909 | yes | Codetext | m² | Trockenbauarbeiten | Wand | Installationswand | WI-IW | 0 | A | 7.5 | 1213HWa0812968250 | NEW | no | no | 0 | 0 | no | 47 | no | Codetext | AllplanAttributes - Ortscode_Geschoßbezeichnung: E02; W_Deckenanschluss: Gleitender Deckenanschluss Fall 03; ash_W_Trockenbau_Qualitäten: 11
 | H2 Ebene +2 | WI-IW | 1213Wa 0812970850 | yes | Codetext | m² | Trockenbauarbeiten | Wand | Installationswand | WI-IW | 0 | A | 7.5 | 1213HWa0812968248 | NEW | no | no | 0 | 0 | no | 0 | no | Codetext | AllplanAttributes - Ortscode_Geschoßbezeichnung: E02; W_Deckenanschluss: Gleitender Deckenanschluss Fall 03; ash_W_Trockenbau_Qualitäten: 2
 | H2 Ebene +2 | Installationsraum | 1213Wa 0812970884 | yes | Codetext | m² | Trockenbauarbeiten | Wand | Installationswand | Installationsraum | 0 | A | 7.5 | 1213HWa0812968248 | NEW | no | no | 0 | 0 | no | 0 | no | Codetext | AllplanAttributes - Ortscode_Geschoßbezeichnung: E02
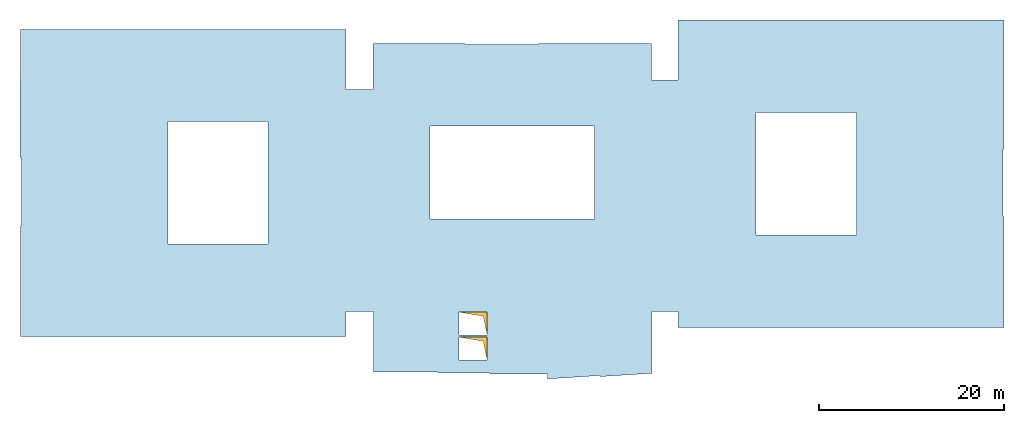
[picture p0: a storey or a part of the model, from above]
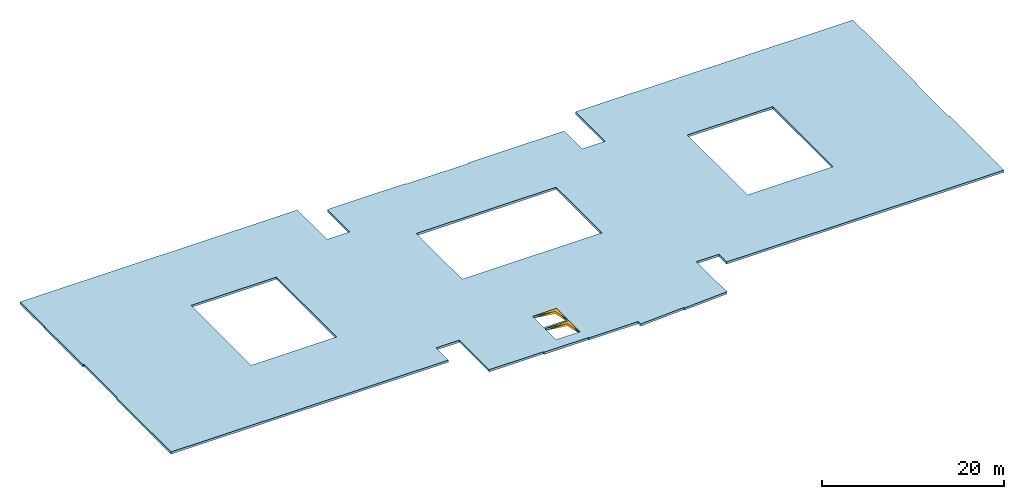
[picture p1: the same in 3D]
Properties of the parts of a building model (IFC4), part 57 of 80

# IfcWall (6826)
Name | In | Material | Allright_Bauteil_ID | 2D Interaktion | Codetext | Abrechnungsart | Gewerk | Objektname | Bezeichnung | AllplanAttributes, Material | Typ = SurfaceSpreadOfFlame | Brandschutzklasse | OKFF | P_ID | Status | LoadBearing | IsExternal | FireRating | ThermalTransmittance (W/K/m2) | Combustible | AcousticRating | Compartmentation | Reference
 | H2 Ebene +2 | Installationsraum | 1213Wa 0812970648 | yes | Codetext | m² | Trockenbauarbeiten | Wand | Installationswand | Installationsraum | 0 | A | 7.5 | 1213HWa0812968248 | NEW | no | no | 0 | 0 | no | 0 | no | Codetext | AllplanAttributes - Ortscode_Geschoßbezeichnung: E02
 | H2 Ebene +2 | WI-IW | 1213Wa 0812970870 | yes | Codetext | m² | Trockenbauarbeiten | Wand | Installationswand | WI-IW | 0 | A | 7.5 | 1213HWa0812968248 | NEW | no | no | 0 | 0 | no | 0 | no | Codetext | AllplanAttributes - Ortscode_Geschoßbezeichnung: E02; W_Deckenanschluss: Gleitender Deckenanschluss Fall 03; ash_W_Trockenbau_Qualitäten: 2
 | H2 Ebene +2 | WI-LB | 1213Wa 0812986044 | yes | Codetext | m² | Trockenbauarbeiten | Wand | Innenwand 1-Schalig | WI-LB | 0 | A | 7.5 | 1213HWa0812968129 | NEW | no | no | REI 60-A1 - D,s2-d0 /A1 | 0 | no | 47 | no | Codetext | AllplanAttributes - Ortscode_Geschoßbezeichnung: E02; ash_W_Trockenbau_Qualitäten: 6; Sicherheitsklasse: -
 | H2 Ebene +2 | WI-HW 60 | 1213Wa 0813089233 | yes | Codetext | m² | Zimmer- und Holzbauarbeiten | Wand | Innenwand 1-Schalig | WI-HW 60 | 0 | A | 7.5 | 1213HWa0812968129 | NEW | no | no | REI 60-A1 - D,s2-d0 +A1 | 0 | no | 47 | no | Codetext | AllplanAttributes - Ortscode_Geschoßbezeichnung: E02; Sicherheitsklasse: -; ash W_laufende Nr. Statik: 1 (W 1.0/ 1.1/ 1.2)
 | H2 Ebene +2 | WI-HW 60 | 1213Wa 0812970656 | yes | Codetext | m² | Zimmer- und Holzbauarbeiten | Wand | Innenwand 1-Schalig | WI-HW 60 | 0 | A | 7.5 | 1213HWa0812968229 | NEW | no | no | REI 60-A1 - D,s2-d0 +A1 | 0 | no | 47 | no | Codetext | AllplanAttributes - Ortscode_Geschoßbezeichnung: E02; Sicherheitsklasse: -; ash W_laufende Nr. Statik: 3 (W 3.0)
 | H2 Ebene +2 | WI-LB | 1213Wa 0813089028 | yes | Codetext | m² | Trockenbauarbeiten | Wand | Innenwand 1-Schalig | WI-LB | 0 | A | 7.5 | 1213HWa0812968229 | NEW | no | no | REI 60-A1 - D,s2-d0 /A1 | 0 | no | 47 | no | Codetext | AllplanAttributes - Ortscode_Geschoßbezeichnung: E02; ash_W_Trockenbau_Qualitäten: 6; Sicherheitsklasse: -
 | H2 Ebene +2 | WI-HW 60 | 1213Wa 0813663750 | yes | Codetext | m² | Zimmer- und Holzbauarbeiten | Wand | Innenwand 1-Schalig | WI-HW 60 | 0 | A | 7.5 | 1213HWa0812968229 | NEW | no | no | REI 60-A1 - D,s2-d0 +A1 | 0 | no | 47 | no | Codetext | AllplanAttributes - Ortscode_Geschoßbezeichnung: E02; Sicherheitsklasse: -; ash W_laufende Nr. Statik: 3 (W 3.0)
 | H2 Ebene +2 | WI-HW 60 | 1213Wa 0813656589 | yes | Codetext | m² | Zimmer- und Holzbauarbeiten | Wand | Innenwand 1-Schalig | WI-HW 60 | 0 | A | 7.5 | 1213HWa0812968129 | NEW | no | no | REI 60-A1 - D,s2-d0 +A1 | 0 | no | 47 | no | Codetext | AllplanAttributes - Ortscode_Geschoßbezeichnung: E02; Sicherheitsklasse: -; ash W_laufende Nr. Statik: 1 (W 1.0/ 1.1/ 1.2)
 | H2 Ebene +2 | Installationsraum | 1213Wa 0812970650 | yes | Codetext | m² | Trockenbauarbeiten | Wand | Installationswand | Installationsraum | 0 | A | 7.5 | 1213HWa0812968233 | NEW | no | no | 0 | 0 | no | 0 | no | Codetext | AllplanAttributes - Ortscode_Geschoßbezeichnung: E02
 | H2 Ebene +2 | WI-VS | 1213Wa 0812970911 | yes | Codetext | m² | Trockenbauarbeiten | Wand | Installationswand | WI-VS | 0 | A | 7.5 | 1213HWa0812968233 | NEW | no | no | 0 | 0 | no | 0 | no | Codetext | AllplanAttributes - Ortscode_Geschoßbezeichnung: E02; W_Deckenanschluss: Gleitender Deckenanschluss Fall 03; ash_W_Trockenbau_Qualitäten: 2
 | H2 Ebene +2 | WI-LB | 1213Wa 0812986041 | yes | Codetext | m² | Trockenbauarbeiten | Wand | Innenwand 1-Schalig | WI-LB | 0 | A | 7.5 | 1213HWa0812968554 | NEW | no | no | 0 | 0 | no | 0 | no | Codetext | AllplanAttributes - Ortscode_Geschoßbezeichnung: E02; W_Deckenanschluss: Gleitender Deckenanschluss Fall 01; ash_W_Trockenbau_Qualitäten: 12b
 | H2 Ebene +2 | WI-LB | 1213Wa 0813569413 | yes | Codetext | m² | Trockenbauarbeiten | Wand | Innenwand 1-Schalig | WI-LB | 0 | A | 7.5 | 1213HWa0812968095 | NEW |  | no | 0 | 0 | no |  | no | Codetext | AllplanAttributes - Ortscode_Geschoßbezeichnung: E02; W_Deckenanschluss: Gleitender Deckenanschluss Fall 01; ash_W_Trockenbau_Qualitäten: 18
 | H2 Ebene +2 | WI-LB | 1213Wa 0813664185 | yes | Codetext | m² | Trockenbauarbeiten | Wand | Innenwand 1-Schalig | WI-LB | 0 | A | 7.5 | 1213HWa0812968095 | NEW |  | no | 0 | 0 | no |  | no | Codetext | AllplanAttributes - Ortscode_Geschoßbezeichnung: E02; W_Deckenanschluss: Gleitender Deckenanschluss Fall 01; ash_W_Trockenbau_Qualitäten: 18
 | H2 Ebene +2 | WI-LB | 1213Wa 0813664196 | yes | Codetext | m² | Trockenbauarbeiten | Wand | Innenwand 1-Schalig | WI-LB | 0 | A | 7.5 | 1213HWa0812968095 | NEW |  | no | 0 | 0 | no |  | no | Codetext | AllplanAttributes - Ortscode_Geschoßbezeichnung: E02; W_Deckenanschluss: Gleitender Deckenanschluss Fall 01; ash_W_Trockenbau_Qualitäten: 18
 | H2 Ebene +2 | WI-LB | 1213Wa 0813664208 | yes | Codetext | m² | Trockenbauarbeiten | Wand | Innenwand 1-Schalig | WI-LB | 0 | A | 7.5 | 1213HWa0812968095 | NEW |  | no | 0 | 0 | no |  | no | Codetext | AllplanAttributes - Ortscode_Geschoßbezeichnung: E02; W_Deckenanschluss: Gleitender Deckenanschluss Fall 01; ash_W_Trockenbau_Qualitäten: 18
 | H2 Ebene +2 | WI-LB | 1213Wa 0813664177 | yes | Codetext | m² | Trockenbauarbeiten | Wand | Innenwand 1-Schalig | WI-LB | 0 | A | 7.5 | 1213HWa0812968095 | NEW |  | no | 0 | 0 | no |  | no | Codetext | AllplanAttributes - Ortscode_Geschoßbezeichnung: E02; W_Deckenanschluss: Gleitender Deckenanschluss Fall 01; ash_W_Trockenbau_Qualitäten: 18
 | H2 Ebene +2 | WI-LB | 1213Wa 0813664274 | yes | Codetext | m² | Trockenbauarbeiten | Wand | Innenwand 1-Schalig | WI-LB | 0 | A | 7.5 | 1213HWa0812968095 | NEW |  | no | 0 | 0 | no |  | no | Codetext | AllplanAttributes - Ortscode_Geschoßbezeichnung: E02; W_Deckenanschluss: Gleitender Deckenanschluss Fall 01; ash_W_Trockenbau_Qualitäten: 6
 | H2 Ebene +2 | WI-LB | 1213Wa 0813664318 | yes | Codetext | m² | Trockenbauarbeiten | Wand | Innenwand 1-Schalig | WI-LB | 0 | A | 7.5 | 1213HWa0812968095 | NEW |  | no | 0 | 0 | no |  | no | Codetext | AllplanAttributes - Ortscode_Geschoßbezeichnung: E02; W_Deckenanschluss: Gleitender Deckenanschluss Fall 01; ash_W_Trockenbau_Qualitäten: 6
 | H2 Ebene +2 | WI-LB | 1213Wa 0813664329 | yes | Codetext | m² | Trockenbauarbeiten | Wand | Innenwand 1-Schalig | WI-LB | 0 | A | 7.5 | 1213HWa0812968095 | NEW |  | no | 0 | 0 | no |  | no | Codetext | AllplanAttributes - Ortscode_Geschoßbezeichnung: E02; W_Deckenanschluss: Gleitender Deckenanschluss Fall 01; ash_W_Trockenbau_Qualitäten: 6
 | H2 Ebene +2 | WI-PR | 1213Wa 0813664335 | yes | Codetext | m² | Trockenbauarbeiten | Wand | "BS-Beplankung; 2-fach Gipsfaserplatten" | WI-PR | 0 | A | 7.5 | 1163HWa0812836365 | NEW |  | no |  | 0 | no | 0 | no | Codetext | AllplanAttributes - Ortscode_Geschoßbezeichnung: E02; Positionsnummer_Text: U100
 | H2 Ebene +2 | WI-PR | 1213Wa 0813664340 | yes | Codetext | m² | Trockenbauarbeiten | Wand | "BS-Beplankung; 2-fach Gipsfaserplatten" | WI-PR | 0 | A | 7.5 | 1163HWa0812836365 | NEW |  | no |  | 0 | no | 0 | no | Codetext | AllplanAttributes - Ortscode_Geschoßbezeichnung: E02; Positionsnummer_Text: U100
 | H2 Ebene +2 | WI-PR | 1213Wa 0813664350 | yes | Codetext | m² | Trockenbauarbeiten | Wand | "BS-Beplankung; 2-fach Gipsfaserplatten" | WI-PR | 0 | A | 7.5 | 1163HWa0812836365 | NEW |  | no |  | 0 | no | 0 | no | Codetext | AllplanAttributes - Ortscode_Geschoßbezeichnung: E02; Positionsnummer_Text: U100
 | H2 Ebene +2 | WI-PR | 1213Wa 0813664362 | yes | Codetext | m² | Trockenbauarbeiten | Wand | "BS-Beplankung; 2-fach Gipsfaserplatten" | WI-PR | 0 | A | 7.5 | 1163HWa0812836365 | NEW |  | no |  | 0 | no | 0 | no | Codetext | AllplanAttributes - Ortscode_Geschoßbezeichnung: E02; Positionsnummer_Text: U100
 | H2 Ebene +2 | WI-PR | 1213Wa 0813664389 | yes | Codetext | m² | Trockenbauarbeiten | Wand | "BS-Beplankung; 2-fach Gipsfaserplatten" | WI-PR | 0 | A | 7.5 | 1163HWa0812836365 | NEW |  | no |  | 0 | no | 0 | no | Codetext | AllplanAttributes - Ortscode_Geschoßbezeichnung: E02; Positionsnummer_Text: U100
 | H2 Ebene +2 | WI-PR | 1213Wa 0813664394 | yes | Codetext | m² | Trockenbauarbeiten | Wand | "BS-Beplankung; 2-fach Gipsfaserplatten" | WI-PR | 0 | A | 7.5 | 1163HWa0812836365 | NEW |  | no |  | 0 | no | 0 | no | Codetext | AllplanAttributes - Ortscode_Geschoßbezeichnung: E02; Positionsnummer_Text: U100
 | H2 Ebene +2 | WI-PR | 1213Wa 0813664392 | yes | Codetext | m² | Trockenbauarbeiten | Wand | "BS-Beplankung; 2-fach Gipsfaserplatten" | WI-PR | 0 | A | 7.5 | 1163HWa0812836365 | NEW |  | no |  | 0 | no | 0 | no | Codetext | AllplanAttributes - Ortscode_Geschoßbezeichnung: E02; Positionsnummer_Text: U100
 | H2 Ebene +2 | WI-LB | 1213Wa 0813664382 | yes | Codetext | m² | Trockenbauarbeiten | Wand | Innenwand 1-Schalig | WI-LB | 0 | A | 7.5 | 1213HWa0812968095 | NEW |  | no | 0 | 0 | no |  | no | Codetext | AllplanAttributes - Ortscode_Geschoßbezeichnung: E02; W_Deckenanschluss: Gleitender Deckenanschluss Fall 01; ash_W_Trockenbau_Qualitäten: 6
 | H2 Ebene +2 | WI-PR | 1213Wa 0813664391 | yes | Codetext | m² | Trockenbauarbeiten | Wand | "BS-Beplankung; 2-fach Gipsfaserplatten" | WI-PR | 0 | A | 7.5 | 1163HWa0812836365 | NEW |  | no |  | 0 | no | 0 | no | Codetext | AllplanAttributes - Ortscode_Geschoßbezeichnung: E02; Positionsnummer_Text: U100
 | H2 Ebene +2 | WI-LB | 1213Wa 0813664418 | yes | Codetext | m² | Trockenbauarbeiten | Wand | Innenwand 1-Schalig | WI-LB | 0 | A | 7.5 | 1213HWa0812968095 | NEW |  | no | 0 | 0 | no |  | no | Codetext | AllplanAttributes - Ortscode_Geschoßbezeichnung: E02; W_Deckenanschluss: Gleitender Deckenanschluss Fall 01; ash_W_Trockenbau_Qualitäten: 6
 | H2 Ebene +2 | WI-LB | 1213Wa 0812986288 | yes | Codetext | m² | Trockenbauarbeiten | Wand | Innenwand 1-Schalig | WI-LB | 0 | A | 7.5 | 1213HWa0812968095 | NEW |  | no | 0 | 0 | no | 47 | no | Codetext | AllplanAttributes - Ortscode_Geschoßbezeichnung: E02; W_Deckenanschluss: Gleitender Deckenanschluss Fall 01; ash_W_Trockenbau_Qualitäten: 1e
 | H2 Ebene +2 | WI-LB | 1213Wa 0812986283 | yes | Codetext | m² | Trockenbauarbeiten | Wand | Innenwand 1-Schalig | WI-LB | 0 | A | 7.5 | 1213HWa0812968272 | NEW |  | no | 0 | 0 | no | 47 | no | Codetext | AllplanAttributes - Ortscode_Geschoßbezeichnung: E02; W_Deckenanschluss: Gleitender Deckenanschluss Fall 01; ash_W_Trockenbau_Qualitäten: 1e
 | H2 Ebene +2 | WI-IW | 1213Wa 0812970800 | yes | Codetext | m² | Trockenbauarbeiten | Wand | Installationswand | WI-IW | 0 | A | 7.5 | 1213HWa0812968275 | NEW |  | no | 0 | 0 | no | 0 | no | Codetext | AllplanAttributes - Ortscode_Geschoßbezeichnung: E02; W_Deckenanschluss: Gleitender Deckenanschluss Fall 01; ash_W_Trockenbau_Qualitäten: 18
 | H2 Ebene +2 | Installationsraum | 1213Wa 0812970802 | yes | Codetext | m² | Trockenbauarbeiten | Wand | Installationswand | Installationsraum | 0 | A | 7.5 | 1213HWa0812968275 | NEW |  | no | 0 | 0 | no | 0 | no | Codetext | AllplanAttributes - Ortscode_Geschoßbezeichnung: E02
 | H2 Ebene +2 | WI-IW | 1213Wa 0812970798 | yes | Codetext | m² | Trockenbauarbeiten | Wand | Installationswand | WI-IW | 0 | A | 7.5 | 1213HWa0812968276 | NEW |  | no | 0 | 0 | no | 0 | no | Codetext | AllplanAttributes - Ortscode_Geschoßbezeichnung: E02; W_Deckenanschluss: Gleitender Deckenanschluss Fall 01; ash_W_Trockenbau_Qualitäten: 18
 | H2 Ebene +2 | WI-LB | 1213Wa 0813665104 | yes | Codetext | m² | Trockenbauarbeiten | Wand | Innenwand 1-Schalig | WI-LB | 0 | A | 7.5 | 1213HWa0812968436 | NEW | no | no | REI 60-A1 - D,s2-d0 /A1 | 0 | no | 0 | no | Codetext | AllplanAttributes - Ortscode_Geschoßbezeichnung: E02; ash_W_Trockenbau_Qualitäten: 9
 | H2 Ebene +2 | WI-LB | 1213Wa 0813665111 | yes | Codetext | m² | Trockenbauarbeiten | Wand | Innenwand 1-Schalig | WI-LB | 0 | A | 7.5 | 1213HWa0812968436 | NEW | no | no | REI 60-A1 - D,s2-d0 /A1 | 0 | no | 0 | no | Codetext | AllplanAttributes - Ortscode_Geschoßbezeichnung: E02; ash_W_Trockenbau_Qualitäten: 9
 | H2 Ebene +2 | WI-LB | 1213Wa 0813665262 | yes | Codetext | m² | Trockenbauarbeiten | Wand | Innenwand 1-Schalig | WI-LB | 0 | A | 7.5 | 1213HWa0812968446 | NEW | no | no | REI 60-A1 - D,s2-d0 /A1 | 0 | no | 0 | no | Codetext | AllplanAttributes - Ortscode_Geschoßbezeichnung: E02; ash_W_Trockenbau_Qualitäten: 9
 | H2 Ebene +2 | WI-LB | 1213Wa 0813665269 | yes | Codetext | m² | Trockenbauarbeiten | Wand | Innenwand 1-Schalig | WI-LB | 0 | A | 7.5 | 1213HWa0812968446 | NEW | no | no | REI 60-A1 - D,s2-d0 /A1 | 0 | no | 0 | no | Codetext | AllplanAttributes - Ortscode_Geschoßbezeichnung: E02; ash_W_Trockenbau_Qualitäten: 9
 | H2 Ebene +2 | Installationsraum | 1213Wa 0812970954 | yes | Codetext | m² | Trockenbauarbeiten | Wand | Installationswand | Installationsraum | 0 | A | 7.5 | 1213HWa0812968149 | NEW |  | no | 0 | 0 | no | 0 | no | Codetext | AllplanAttributes - Ortscode_Geschoßbezeichnung: E02
 | H2 Ebene +2 | WI-VS | 1213Wa 0812970956 | yes | Codetext | m² | Trockenbauarbeiten | Wand | Installationswand | WI-VS | 0 | A | 7.5 | 1213HWa0812968149 | NEW |  | no | 0 | 0 | no | 0 | no | Codetext | AllplanAttributes - Ortscode_Geschoßbezeichnung: E02; W_Deckenanschluss: Gleitender Deckenanschluss Fall 01; ash_W_Trockenbau_Qualitäten: 18
 | H2 Ebene +2 | WI-VS | 1213Wa 0813665392 | yes | Codetext | m² | Trockenbauarbeiten | Wand | Installationswand | WI-VS | 0 | A | 7.5 | 1213HWa0812968149 | NEW |  | no | 0 | 0 | no | 0 | no | Codetext | AllplanAttributes - Ortscode_Geschoßbezeichnung: E02; W_Deckenanschluss: Gleitender Deckenanschluss Fall 01; ash_W_Trockenbau_Qualitäten: 18
 | H2 Ebene +2 | WI-IW | 1213Wa 0812970505 | yes | Codetext | m² | Trockenbauarbeiten | Wand | Installationswand | WI-IW | 0 | A | 7.5 | 1213HWa0812968463 | NEW |  | no | 0 | 0 | no | 0 | no | Codetext | AllplanAttributes - Ortscode_Geschoßbezeichnung: E02; W_Deckenanschluss: Gleitender Deckenanschluss Fall 01; ash_W_Trockenbau_Qualitäten: 18
 | H2 Ebene +2 | WI-IW | 1213Wa 0812970507 | yes | Codetext | m² | Trockenbauarbeiten | Wand | Installationswand | WI-IW | 0 | A | 7.5 | 1213HWa0812968100 | NEW |  | no | 0 | 0 | no | 0 | no | Codetext | AllplanAttributes - Ortscode_Geschoßbezeichnung: E02; W_Deckenanschluss: Gleitender Deckenanschluss Fall 01; ash_W_Trockenbau_Qualitäten: 18
 | H2 Ebene +2 | Installationsraum | 1213Wa 0812970509 | yes | Codetext | m² | Trockenbauarbeiten | Wand | Installationswand | Installationsraum | 0 | A | 7.5 | 1213HWa0812968100 | NEW |  | no | 0 | 0 | no | 0 | no | Codetext | AllplanAttributes - Ortscode_Geschoßbezeichnung: E02
 | H2 Ebene +2 | WI-STB | 1213Wa 0812970515 | yes | Codetext | m² | Zimmer- und Holzbauarbeiten | Wand | Außenwand 1-Schalig | WI-STB | 0 | A | 7.5 | 1213HWa0812968455 | NEW |  | no | REI 60-A1 - D,s2-d0 /A1 | 0 | no | 52 | no | Codetext | AllplanAttributes - Ortscode_Geschoßbezeichnung: E02
 | H2 Ebene +2 | Installationsraum | 1213Wa 0812970577 | yes | Codetext | m² | Trockenbauarbeiten | Wand | Installationswand | Installationsraum | 0 | A | 7.5 | 1213HWa0812968248 | NEW | no | no | 0 | 0 | no | 0 | no | Codetext | AllplanAttributes - Ortscode_Geschoßbezeichnung: E02
 | H2 Ebene +2 | WI-IW | 1213Wa 0812970575 | yes | Codetext | m² | Trockenbauarbeiten | Wand | Installationswand | WI-IW | 0 | A | 7.5 | 1213HWa0812968248 | NEW | no | no | 0 | 0 | no | 0 | no | Codetext | AllplanAttributes - Ortscode_Geschoßbezeichnung: E02; W_Deckenanschluss: Gleitender Deckenanschluss Fall 03; ash_W_Trockenbau_Qualitäten: 2
 | H2 Ebene +2 | WI-LB | 1213Wa 0812986009 | yes | Codetext | m² | Trockenbauarbeiten | Wand | Innenwand 1-Schalig | WI-LB | 0 | A | 7.5 | 1213HWa0812968367 | NEW | no | no | 0 | 0 | no | 0 | no | Codetext | AllplanAttributes - Ortscode_Geschoßbezeichnung: E02; W_Deckenanschluss: Gleitender Deckenanschluss Fall 01; ash_W_Trockenbau_Qualitäten: 12b
 | H2 Ebene +2 | WI-LB | 1213Wa 0812986199 |  | Codetext | m² | Trockenbauarbeiten | Wand |  |  | 0 | A | 7.5 | 1213HWa0812968360 | NEW | no | no | 0 | 0 | no | 0 | no | Codetext | AllplanAttributes - Ortscode_Geschoßbezeichnung: E02; W_Deckenanschluss: Gleitender Deckenanschluss Fall 03; ash_W_Trockenbau_Qualitäten: 10a
 | H2 Ebene +2 | WI-HW 60 | 1213Wa 0813666223 | yes | Codetext | m² | Zimmer- und Holzbauarbeiten | Wand | Innenwand 1-Schalig | WI-HW 60 | 0 | A | 7.5 | 1213HWa0812968164 | NEW | no | no | REI 60-A1 - D,s2-d0 +A1 | 0 | no | 47 | no | Codetext | AllplanAttributes - Ortscode_Geschoßbezeichnung: E02; Sicherheitsklasse: -; ash W_laufende Nr. Statik: 1 (W 1.0/ 1.1/ 1.2)
 | H2 Ebene +2 | WI-HW 60 | 1213Wa 0813666237 | yes | Codetext | m² | Zimmer- und Holzbauarbeiten | Wand | Innenwand 1-Schalig | WI-HW 60 | 0 | A | 7.5 | 1213HWa0812968164 | NEW | no | no | REI 60-A1 - D,s2-d0 +A1 | 0 | no | 47 | no | Codetext | AllplanAttributes - Ortscode_Geschoßbezeichnung: E02; Sicherheitsklasse: -; ash W_laufende Nr. Statik: 1 (W 1.0/ 1.1/ 1.2)
 | H2 Ebene +2 | WI-LB | 1213Wa 0813666349 | yes | Codetext | m² | Trockenbauarbeiten | Wand | Innenwand 1-Schalig | WI-LB | 0 | A | 7.5 | 1213HWa0812968095 | NEW |  | no | 0 | 0 | no |  | no | Codetext | AllplanAttributes - Ortscode_Geschoßbezeichnung: E02; W_Deckenanschluss: Gleitender Deckenanschluss Fall 01; ash_W_Trockenbau_Qualitäten: 1a
 | H2 Ebene +2 | WI-LB | 1213Wa 0813666370 | yes | Codetext | m² | Trockenbauarbeiten | Wand | Innenwand 1-Schalig | WI-LB | 0 | A | 7.5 | 1213HWa0812968095 | NEW |  | no | 0 | 0 | no |  | no | Codetext | AllplanAttributes - Ortscode_Geschoßbezeichnung: E02; W_Deckenanschluss: Gleitender Deckenanschluss Fall 01; ash_W_Trockenbau_Qualitäten: 18
 | H2 Ebene +2 | WI-LB | 1213Wa 0813666381 | yes | Codetext | m² | Trockenbauarbeiten | Wand | Innenwand 1-Schalig | WI-LB | 0 | A | 7.5 | 1213HWa0812968095 | NEW |  | no | 0 | 0 | no |  | no | Codetext | AllplanAttributes - Ortscode_Geschoßbezeichnung: E02; W_Deckenanschluss: Gleitender Deckenanschluss Fall 01; ash_W_Trockenbau_Qualitäten: 18
 | H2 Ebene +2 | WI-LB | 1213Wa 0813666393 | yes | Codetext | m² | Trockenbauarbeiten | Wand | Innenwand 1-Schalig | WI-LB | 0 | A | 7.5 | 1213HWa0812968095 | NEW |  | no | 0 | 0 | no |  | no | Codetext | AllplanAttributes - Ortscode_Geschoßbezeichnung: E02; W_Deckenanschluss: Gleitender Deckenanschluss Fall 01; ash_W_Trockenbau_Qualitäten: 18
 | H2 Ebene +2 | WI-LB | 1213Wa 0813666359 | yes | Codetext | m² | Trockenbauarbeiten | Wand | Innenwand 1-Schalig | WI-LB | 0 | A | 7.5 | 1213HWa0812968095 | NEW |  | no | 0 | 0 | no |  | no | Codetext | AllplanAttributes - Ortscode_Geschoßbezeichnung: E02; W_Deckenanschluss: Gleitender Deckenanschluss Fall 01; ash_W_Trockenbau_Qualitäten: 18
 | H2 Ebene +2 | WI-LB | 1213Wa 0813054677 | yes | Codetext | m² | Trockenbauarbeiten | Wand | Innenwand 1-Schalig | WI-LB | 0 | A | 7.5 | 1213HWa0813054675 | NEW | no | no | 0 | 0 | no | 0 | no | Codetext | AllplanAttributes - Ortscode_Geschoßbezeichnung: E02; ash_W_Trockenbau_Qualitäten: 8
 | H2 Ebene +2 | WI-IW | 1213Wa 0812970271 | yes | Codetext | m² | Trockenbauarbeiten | Wand | Installationswand | WI-IW | 0 | A | 7.5 | 1213HWa0812968248 | NEW | no | no | 0 | 0 | no | 0 | no | Codetext | AllplanAttributes - Ortscode_Geschoßbezeichnung: E02; W_Deckenanschluss: Gleitender Deckenanschluss Fall 03; ash_W_Trockenbau_Qualitäten: 2
 | H2 Ebene +2 | Installationsraum | 1213Wa 0812970610 | yes | Codetext | m² | Trockenbauarbeiten | Wand | Installationswand | Installationsraum | 0 | A | 7.5 | 1213HWa0812968248 | NEW | no | no | 0 | 0 | no | 0 | no | Codetext | AllplanAttributes - Ortscode_Geschoßbezeichnung: E02
 | H2 Ebene +2 | WI-IW | 1213Wa 0812970584 | yes | Codetext | m² | Trockenbauarbeiten | Wand | Installationswand | WI-IW | 0 | A | 7.5 | 1213HWa0812968250 | NEW | no | no | 0 | 0 | no | 47 | no | Codetext | AllplanAttributes - Ortscode_Geschoßbezeichnung: E02; W_Deckenanschluss: Gleitender Deckenanschluss Fall 03; ash_W_Trockenbau_Qualitäten: 11
 | H2 Ebene +2 | Installationsraum | 1213Wa 0812970588 | yes | Codetext | m² | Trockenbauarbeiten | Wand | Installationswand | Installationsraum | 0 | A | 7.5 | 1213HWa0812968250 | NEW | no | no | 0 | 0 | no | 0 | no | Codetext | AllplanAttributes - Ortscode_Geschoßbezeichnung: E02
 | H2 Ebene +2 | WI-IW | 1213Wa 0812970586 | yes | Codetext | m² | Trockenbauarbeiten | Wand | Installationswand | WI-IW | 0 | A | 7.5 | 1213HWa0812968250 | NEW | no | no | 0 | 0 | no | 47 | no | Codetext | AllplanAttributes - Ortscode_Geschoßbezeichnung: E02; W_Deckenanschluss: Gleitender Deckenanschluss Fall 03; ash_W_Trockenbau_Qualitäten: 11
 | H2 Ebene +2 | WI-IW | 1213Wa 0812970669 | yes | Codetext | m² | Trockenbauarbeiten | Wand | Installationswand | WI-IW | 0 | A | 7.5 | 1213HWa0812968248 | NEW | no | no | 0 | 0 | no | 0 | no | Codetext | AllplanAttributes - Ortscode_Geschoßbezeichnung: E02; W_Deckenanschluss: Gleitender Deckenanschluss Fall 03; ash_W_Trockenbau_Qualitäten: 2
 | H2 Ebene +2 | Installationsraum | 1213Wa 0812970582 | yes | Codetext | m² | Trockenbauarbeiten | Wand | Installationswand | Installationsraum | 0 | A | 7.5 | 1213HWa0812968248 | NEW | no | no | 0 | 0 | no | 0 | no | Codetext | AllplanAttributes - Ortscode_Geschoßbezeichnung: E02
 | H2 Ebene +2 | WI-IW | 1213Wa 0812970715 | yes | Codetext | m² | Trockenbauarbeiten | Wand | Installationswand | WI-IW | 0 | A | 7.5 | 1213HWa0812968248 | NEW | no | no | 0 | 0 | no | 0 | no | Codetext | AllplanAttributes - Ortscode_Geschoßbezeichnung: E02; W_Deckenanschluss: Gleitender Deckenanschluss Fall 03; ash_W_Trockenbau_Qualitäten: 2
 | H2 Ebene +2 | Installationsraum | 1213Wa 0812970604 | yes | Codetext | m² | Trockenbauarbeiten | Wand | Installationswand | Installationsraum | 0 | A | 7.5 | 1213HWa0812968248 | NEW | no | no | 0 | 0 | no | 0 | no | Codetext | AllplanAttributes - Ortscode_Geschoßbezeichnung: E02
 | H2 Ebene +2 | WI-IW | 1213Wa 0812970594 | yes | Codetext | m² | Trockenbauarbeiten | Wand | Installationswand | WI-IW | 0 | A | 7.5 | 1213HWa0812968250 | NEW | no | no | 0 | 0 | no | 47 | no | Codetext | AllplanAttributes - Ortscode_Geschoßbezeichnung: E02; W_Deckenanschluss: Gleitender Deckenanschluss Fall 03; ash_W_Trockenbau_Qualitäten: 11
 | H2 Ebene +2 | Installationsraum | 1213Wa 0812970592 | yes | Codetext | m² | Trockenbauarbeiten | Wand | Installationswand | Installationsraum | 0 | A | 7.5 | 1213HWa0812968250 | NEW | no | no | 0 | 0 | no | 0 | no | Codetext | AllplanAttributes - Ortscode_Geschoßbezeichnung: E02
 | H2 Ebene +2 | WI-IW | 1213Wa 0812970590 | yes | Codetext | m² | Trockenbauarbeiten | Wand | Installationswand | WI-IW | 0 | A | 7.5 | 1213HWa0812968250 | NEW | no | no | 0 | 0 | no | 47 | no | Codetext | AllplanAttributes - Ortscode_Geschoßbezeichnung: E02; W_Deckenanschluss: Gleitender Deckenanschluss Fall 03; ash_W_Trockenbau_Qualitäten: 11
 | H2 Ebene +2 | WI-IW | 1213Wa 0812970713 | yes | Codetext | m² | Trockenbauarbeiten | Wand | Installationswand | WI-IW | 0 | A | 7.5 | 1213HWa0812968248 | NEW | no | no | 0 | 0 | no | 0 | no | Codetext | AllplanAttributes - Ortscode_Geschoßbezeichnung: E02; W_Deckenanschluss: Gleitender Deckenanschluss Fall 03; ash_W_Trockenbau_Qualitäten: 2
 | H2 Ebene +2 | Installationsraum | 1213Wa 0812970602 | yes | Codetext | m² | Trockenbauarbeiten | Wand | Installationswand | Installationsraum | 0 | A | 7.5 | 1213HWa0812968248 | NEW | no | no | 0 | 0 | no | 0 | no | Codetext | AllplanAttributes - Ortscode_Geschoßbezeichnung: E02
 | H2 Ebene +2 | WI-IW | 1213Wa 0812970719 | yes | Codetext | m² | Trockenbauarbeiten | Wand | Installationswand | WI-IW | 0 | A | 7.5 | 1213HWa0812968248 | NEW | no | no | 0 | 0 | no | 0 | no | Codetext | AllplanAttributes - Ortscode_Geschoßbezeichnung: E02; W_Deckenanschluss: Gleitender Deckenanschluss Fall 03; ash_W_Trockenbau_Qualitäten: 2
 | H2 Ebene +2 | Installationsraum | 1213Wa 0812970608 | yes | Codetext | m² | Trockenbauarbeiten | Wand | Installationswand | Installationsraum | 0 | A | 7.5 | 1213HWa0812968248 | NEW | no | no | 0 | 0 | no | 0 | no | Codetext | AllplanAttributes - Ortscode_Geschoßbezeichnung: E02
 | H2 Ebene +2 | WI-IW | 1213Wa 0812970600 | yes | Codetext | m² | Trockenbauarbeiten | Wand | Installationswand | WI-IW | 0 | A | 7.5 | 1213HWa0812968250 | NEW | no | no | 0 | 0 | no | 47 | no | Codetext | AllplanAttributes - Ortscode_Geschoßbezeichnung: E02; W_Deckenanschluss: Gleitender Deckenanschluss Fall 03; ash_W_Trockenbau_Qualitäten: 11
 | H2 Ebene +2 | Installationsraum | 1213Wa 0812970596 | yes | Codetext | m² | Trockenbauarbeiten | Wand | Installationswand | Installationsraum | 0 | A | 7.5 | 1213HWa0812968250 | NEW | no | no | 0 | 0 | no | 0 | no | Codetext | AllplanAttributes - Ortscode_Geschoßbezeichnung: E02
 | H2 Ebene +2 | WI-IW | 1213Wa 0812970598 | yes | Codetext | m² | Trockenbauarbeiten | Wand | Installationswand | WI-IW | 0 | A | 7.5 | 1213HWa0812968250 | NEW | no | no | 0 | 0 | no | 47 | no | Codetext | AllplanAttributes - Ortscode_Geschoßbezeichnung: E02; W_Deckenanschluss: Gleitender Deckenanschluss Fall 03; ash_W_Trockenbau_Qualitäten: 11
 | H2 Ebene +2 | WI-IW | 1213Wa 0812970717 | yes | Codetext | m² | Trockenbauarbeiten | Wand | Installationswand | WI-IW | 0 | A | 7.5 | 1213HWa0812968248 | NEW | no | no | 0 | 0 | no | 0 | no | Codetext | AllplanAttributes - Ortscode_Geschoßbezeichnung: E02; W_Deckenanschluss: Gleitender Deckenanschluss Fall 03; ash_W_Trockenbau_Qualitäten: 2
 | H2 Ebene +2 | Installationsraum | 1213Wa 0812970606 | yes | Codetext | m² | Trockenbauarbeiten | Wand | Installationswand | Installationsraum | 0 | A | 7.5 | 1213HWa0812968248 | NEW | no | no | 0 | 0 | no | 0 | no | Codetext | AllplanAttributes - Ortscode_Geschoßbezeichnung: E02
 | H2 Ebene +2 | WI-LB | 1213Wa 0813667236 | yes | Codetext | m² | Trockenbauarbeiten | Wand | Innenwand 1-Schalig | WI-LB | 0 | A | 7.5 | 1213HWa0812968484 | NEW | no | no | REI 60-A1 - D,s2-d0 /A1 | 0 | no | 0 | no | Codetext | AllplanAttributes - Ortscode_Geschoßbezeichnung: E02; ash_W_Trockenbau_Qualitäten: 9
 | H2 Ebene +2 | WI-LB | 1213Wa 0813667243 | yes | Codetext | m² | Trockenbauarbeiten | Wand | Innenwand 1-Schalig | WI-LB | 0 | A | 7.5 | 1213HWa0812968484 | NEW | no | no | REI 60-A1 - D,s2-d0 /A1 | 0 | no | 0 | no | Codetext | AllplanAttributes - Ortscode_Geschoßbezeichnung: E02; ash_W_Trockenbau_Qualitäten: 9
 | H2 Ebene +2 | WI-LB | 1213Wa 0812986230 | yes | Codetext | m² | Trockenbauarbeiten | Wand | Innenwand 1-Schalig | WI-LB | 0 | A | 7.5 | 1213HWa0812968182 | NEW |  | no | 0 | 0 | no | 47 | no | Codetext | AllplanAttributes - Ortscode_Geschoßbezeichnung: E02; W_Deckenanschluss: Gleitender Deckenanschluss Fall 01; ash_W_Trockenbau_Qualitäten: 1e
 | H2 Ebene +2 | WI-LB | 1213Wa 0812986235 | yes | Codetext | m² | Trockenbauarbeiten | Wand | Innenwand 1-Schalig | WI-LB | 0 | A | 7.5 | 1213HWa0812968183 | NEW |  | no | 0 | 0 | no | 47 | no | Codetext | AllplanAttributes - Ortscode_Geschoßbezeichnung: E02; W_Deckenanschluss: Gleitender Deckenanschluss Fall 01; ash_W_Trockenbau_Qualitäten: 1e
 | H2 Ebene +2 | WI-IW | 1213Wa 0812970643 | yes | Codetext | m² | Trockenbauarbeiten | Wand | Installationswand | WI-IW | 0 | A | 7.5 | 1213HWa0812968369 | NEW |  | no | 0 | 0 | no | 0 | no | Codetext | AllplanAttributes - Ortscode_Geschoßbezeichnung: E02; W_Deckenanschluss: Gleitender Deckenanschluss Fall 01; ash_W_Trockenbau_Qualitäten: 18
 | H2 Ebene +2 | Installationsraum | 1213Wa 0812970641 | yes | Codetext | m² | Trockenbauarbeiten | Wand | Installationswand | Installationsraum | 0 | A | 7.5 | 1213HWa0812968369 | NEW |  | no | 0 | 0 | no | 0 | no | Codetext | AllplanAttributes - Ortscode_Geschoßbezeichnung: E02
 | H2 Ebene +2 | WI-IW | 1213Wa 0812970786 | yes | Codetext | m² | Trockenbauarbeiten | Wand | Installationswand | WI-IW | 0 | A | 7.5 | 1213HWa0812968292 | NEW |  | no | 0 | 0 | no | 0 | no | Codetext | AllplanAttributes - Ortscode_Geschoßbezeichnung: E02; W_Deckenanschluss: Gleitender Deckenanschluss Fall 01; ash_W_Trockenbau_Qualitäten: 18
 | H2 Ebene +2 | Installationsraum | 1213Wa 0812970784 | yes | Codetext | m² | Trockenbauarbeiten | Wand | Installationswand | Installationsraum | 0 | A | 7.5 | 1213HWa0812968292 | NEW |  | no | 0 | 0 | no | 0 | no | Codetext | AllplanAttributes - Ortscode_Geschoßbezeichnung: E02
 | H2 Ebene +2 | WI-IW | 1213Wa 0813667744 | yes | Codetext | m² | Trockenbauarbeiten | Wand | Installationswand | WI-IW | 0 | A | 7.5 | 1213HWa0812968292 | NEW |  | no | 0 | 0 | no | 0 | no | Codetext | AllplanAttributes - Ortscode_Geschoßbezeichnung: E02; W_Deckenanschluss: Gleitender Deckenanschluss Fall 01; ash_W_Trockenbau_Qualitäten: 18
 | H2 Ebene +2 | Installationsraum | 1213Wa 0813667745 | yes | Codetext | m² | Trockenbauarbeiten | Wand | Installationswand | Installationsraum | 0 | A | 7.5 | 1213HWa0812968292 | NEW |  | no | 0 | 0 | no | 0 | no | Codetext | AllplanAttributes - Ortscode_Geschoßbezeichnung: E02
 | H2 Ebene +2 | WI-IW | 1213Wa 0813667811 | yes | Codetext | m² | Trockenbauarbeiten | Wand | Installationswand | WI-IW | 0 | A | 7.5 | 1213HWa0812968120 | NEW |  | no | 0 | 0 | no | 0 | no | Codetext | AllplanAttributes - Ortscode_Geschoßbezeichnung: E02; W_Deckenanschluss: Gleitender Deckenanschluss Fall 01; ash_W_Trockenbau_Qualitäten: 18
 | H2 Ebene +2 | WI-IW | 1213Wa 0812970780 | yes | Codetext | m² | Trockenbauarbeiten | Wand | Installationswand | WI-IW | 0 | A | 7.5 | 1213HWa0812968120 | NEW | no | no | 0 | 0 | no | 0 | no | Codetext | AllplanAttributes - Ortscode_Geschoßbezeichnung: E02; W_Deckenanschluss: Gleitender Deckenanschluss Fall 01; ash_W_Trockenbau_Qualitäten: 18
 | H2 Ebene +2 | Installationsraum | 1213Wa 0812970778 | yes | Codetext | m² | Trockenbauarbeiten | Wand | Installationswand | Installationsraum | 0 | A | 7.5 | 1213HWa0812968120 | NEW | no | no | 0 | 0 | no | 0 | no | Codetext | AllplanAttributes - Ortscode_Geschoßbezeichnung: E02
 | H2 Ebene +2 | WI-LW 60 | 1213Wa 0813156150 | yes | Codetext | m² | Trockenbauarbeiten | Wand | Innenwand 1-Schalig | WI-LW 60 | 0 | A | 7.5 | 1213HWa0813156033 | NEW | yes | no | REI 60-A1 - D,s2-d0 +A1 | 0 | no | 0 | no | Codetext | AllplanAttributes - Ortscode_Geschoßbezeichnung: E02; W_Deckenanschluss: Gleitender Deckenanschluss Fall 01; ash_W_Trockenbau_Qualitäten: 12b
 | H2 Ebene +2 | WI-HW 60 | 1213Wa 0813668170 | yes | Codetext | m² | Zimmer- und Holzbauarbeiten | Wand | Innenwand 1-Schalig | WI-HW 60 | 0 | A | 7.5 | 1213HWa0812968119 | NEW |  | no | 0 | 0 | no | 47 | no | Codetext | AllplanAttributes - Ortscode_Geschoßbezeichnung: E02; Sicherheitsklasse: -; ash W_laufende Nr. Statik: 3 (W 3.0)
 | H2 Ebene +2 | WI-LB | 1213Wa 0813668323 | yes | Codetext | m² | Trockenbauarbeiten | Wand | Innenwand 1-Schalig | WI-LB | 0 | A | 7.5 | 1213HWa0813055490 | NEW | no | no | 0 | 0 | no | 0 | no | Codetext | AllplanAttributes - Ortscode_Geschoßbezeichnung: E02; ash_W_Trockenbau_Qualitäten: 18
 | H2 Ebene +2 | WI-LB | 1213Wa 0813668297 | yes | Codetext | m² | Trockenbauarbeiten | Wand | Innenwand 1-Schalig | WI-LB | 0 | A | 7.5 | 1213HWa0813055490 | NEW | no | no | 0 | 0 | no | 0 | no | Codetext | AllplanAttributes - Ortscode_Geschoßbezeichnung: E02; ash_W_Trockenbau_Qualitäten: 18
 | H2 Ebene +2 | WI-LB | 1213Wa 0813668313 | yes | Codetext | m² | Trockenbauarbeiten | Wand | Innenwand 1-Schalig | WI-LB | 0 | A | 7.5 | 1213HWa0813055490 | NEW | no | no | 0 | 0 | no | 0 | no | Codetext | AllplanAttributes - Ortscode_Geschoßbezeichnung: E02; ash_W_Trockenbau_Qualitäten: 18
 | H2 Ebene +2 | WI-LB | 1213Wa 0813668417 | yes | Codetext | m² | Trockenbauarbeiten | Wand | Innenwand 1-Schalig | WI-LB | 0 | A | 7.5 | 1213HWa0813055490 | NEW | no | no | 0 | 0 | no | 0 | no | Codetext | AllplanAttributes - Ortscode_Geschoßbezeichnung: E02; ash_W_Trockenbau_Qualitäten: 18
 | H2 Ebene +2 | WI-LB | 1213Wa 0813668422 | yes | Codetext | m² | Trockenbauarbeiten | Wand | Innenwand 1-Schalig | WI-LB | 0 | A | 7.5 | 1213HWa0813055490 | NEW | no | no | 0 | 0 | no | 0 | no | Codetext | AllplanAttributes - Ortscode_Geschoßbezeichnung: E02; ash_W_Trockenbau_Qualitäten: 18
 | H2 Ebene +2 | WI-LB | 1213Wa 0813668438 | yes | Codetext | m² | Trockenbauarbeiten | Wand | Innenwand 1-Schalig | WI-LB | 0 | A | 7.5 | 1213HWa0813055490 | NEW | no | no | 0 | 0 | no | 0 | no | Codetext | AllplanAttributes - Ortscode_Geschoßbezeichnung: E02; ash_W_Trockenbau_Qualitäten: 18
 | H2 Ebene +2 | WI-LB | 1213Wa 0813668448 | yes | Codetext | m² | Trockenbauarbeiten | Wand | Innenwand 1-Schalig | WI-LB | 0 | A | 7.5 | 1213HWa0813055490 | NEW | no | no | 0 | 0 | no | 0 | no | Codetext | AllplanAttributes - Ortscode_Geschoßbezeichnung: E02; ash_W_Trockenbau_Qualitäten: 18
 | H2 Ebene +2 | WI-LB | 1213Wa 0812986005 | yes | Codetext | m² | Trockenbauarbeiten | Wand | Innenwand 1-Schalig | WI-LB | 0 | A | 7.5 | 1213HWa0812968175 | NEW | no | no | 0 | 0 | no | 0 | no | Codetext | AllplanAttributes - Ortscode_Geschoßbezeichnung: E02; W_Deckenanschluss: Gleitender Deckenanschluss Fall 01; ash_W_Trockenbau_Qualitäten: 12b
 | H2 Ebene +2 | WI-LB | 1213Wa 0813668688 | yes | Codetext | m² | Trockenbauarbeiten | Wand | Innenwand 1-Schalig | WI-LB | 0 | A | 7.5 | 1213HWa0812968491 | NEW | no | no | REI 60-A1 - D,s2-d0 /A1 | 0 | no | 52 | no | Codetext | AllplanAttributes - Ortscode_Geschoßbezeichnung: E02; ash_W_Trockenbau_Qualitäten: 9
 | H2 Ebene +2 | WI-LB | 1213Wa 0813668697 | yes | Codetext | m² | Trockenbauarbeiten | Wand | Innenwand 1-Schalig | WI-LB | 0 | A | 7.5 | 1213HWa0812968491 | NEW | no | no | REI 60-A1 - D,s2-d0 /A1 | 0 | no |  | no | Codetext | AllplanAttributes - Ortscode_Geschoßbezeichnung: E02; ash_W_Trockenbau_Qualitäten: 9
 | H2 Ebene +2 | WI-HW 60 | 1213Wa 0812986028 | yes | Codetext | m² | Zimmer- und Holzbauarbeiten | Wand | Innenwand 1-Schalig | WI-HW 60 | 0 | A | 7.5 | 1213HWa0812968296 | NEW | no | no | REI 60-A1 - D,s2-d0 +A1 | 0 | no | 47 | no | Codetext | AllplanAttributes - Ortscode_Geschoßbezeichnung: E02; Sicherheitsklasse: -; ash W_laufende Nr. Statik: 1 (W 1.0/ 1.1/ 1.2)
 | H2 Ebene +2 | WI-IW | 1213Wa 0812970770 | yes | Codetext | m² | Trockenbauarbeiten | Wand | Installationswand | WI-IW | 0 | A | 7.5 | 1213HWa0812968321 | NEW | no | no | 0 | 0 | no | 0 | no | Codetext | AllplanAttributes - Ortscode_Geschoßbezeichnung: E02; W_Deckenanschluss: Gleitender Deckenanschluss Fall 03; ash_W_Trockenbau_Qualitäten: 2
 | H2 Ebene +2 | Installationsraum | 1213Wa 0812970772 | yes | Codetext | m² | Trockenbauarbeiten | Wand | Installationswand | Installationsraum | 0 | A | 7.5 | 1213HWa0812968321 | NEW | no | no | 0 | 0 | no | 0 | no | Codetext | AllplanAttributes - Ortscode_Geschoßbezeichnung: E02
 | H2 Ebene +2 | WI-IW | 1213Wa 0812970766 | yes | Codetext | m² | Trockenbauarbeiten | Wand | Installationswand | WI-IW | 0 | A | 7.5 | 1213HWa0812968248 | NEW | no | no | 0 | 0 | no | 0 | no | Codetext | AllplanAttributes - Ortscode_Geschoßbezeichnung: E02; W_Deckenanschluss: Gleitender Deckenanschluss Fall 03; ash_W_Trockenbau_Qualitäten: 2
 | H2 Ebene +2 | Installationsraum | 1213Wa 0812970303 | yes | Codetext | m² | Trockenbauarbeiten | Wand | Installationswand | Installationsraum | 0 | A | 7.5 | 1213HWa0812968248 | NEW | no | no | 0 | 0 | no | 0 | no | Codetext | AllplanAttributes - Ortscode_Geschoßbezeichnung: E02
 | H2 Ebene +2 | WI-IW | 1213Wa 0812970287 | yes | Codetext | m² | Trockenbauarbeiten | Wand | Installationswand | WI-IW | 0 | A | 7.5 | 1213HWa0812968248 | NEW | no | no | 0 | 0 | no | 0 | no | Codetext | AllplanAttributes - Ortscode_Geschoßbezeichnung: E02; W_Deckenanschluss: Gleitender Deckenanschluss Fall 03; ash_W_Trockenbau_Qualitäten: 2
 | H2 Ebene +2 | Installationsraum | 1213Wa 0812970299 | yes | Codetext | m² | Trockenbauarbeiten | Wand | Installationswand | Installationsraum | 0 | A | 7.5 | 1213HWa0812968248 | NEW | no | no | 0 | 0 | no | 0 | no | Codetext | AllplanAttributes - Ortscode_Geschoßbezeichnung: E02
 | H2 Ebene +2 | WI-IW | 1213Wa 0812970688 | yes | Codetext | m² | Trockenbauarbeiten | Wand | Installationswand | WI-IW | 0 | A | 7.5 | 1213HWa0812968250 | NEW | no | no | 0 | 0 | no | 47 | no | Codetext | AllplanAttributes - Ortscode_Geschoßbezeichnung: E02; W_Deckenanschluss: Gleitender Deckenanschluss Fall 03; ash_W_Trockenbau_Qualitäten: 11
 | H2 Ebene +2 | Installationsraum | 1213Wa 0812970686 | yes | Codetext | m² | Trockenbauarbeiten | Wand | Installationswand | Installationsraum | 0 | A | 7.5 | 1213HWa0812968250 | NEW | no | no | 0 | 0 | no | 0 | no | Codetext | AllplanAttributes - Ortscode_Geschoßbezeichnung: E02
 | H2 Ebene +2 | WI-IW | 1213Wa 0812970263 | yes | Codetext | m² | Trockenbauarbeiten | Wand | Installationswand | WI-IW | 0 | A | 7.5 | 1213HWa0812968250 | NEW | no | no | 0 | 0 | no | 47 | no | Codetext | AllplanAttributes - Ortscode_Geschoßbezeichnung: E02; W_Deckenanschluss: Gleitender Deckenanschluss Fall 03; ash_W_Trockenbau_Qualitäten: 11
 | H2 Ebene +2 | WI-IW | 1213Wa 0812970289 | yes | Codetext | m² | Trockenbauarbeiten | Wand | Installationswand | WI-IW | 0 | A | 7.5 | 1213HWa0812968248 | NEW | no | no | 0 | 0 | no | 0 | no | Codetext | AllplanAttributes - Ortscode_Geschoßbezeichnung: E02; W_Deckenanschluss: Gleitender Deckenanschluss Fall 03; ash_W_Trockenbau_Qualitäten: 2
 | H2 Ebene +2 | Installationsraum | 1213Wa 0812970764 | yes | Codetext | m² | Trockenbauarbeiten | Wand | Installationswand | Installationsraum | 0 | A | 7.5 | 1213HWa0812968248 | NEW | no | no | 0 | 0 | no | 0 | no | Codetext | AllplanAttributes - Ortscode_Geschoßbezeichnung: E02
 | H2 Ebene +2 | WI-IW | 1213Wa 0812970291 | yes | Codetext | m² | Trockenbauarbeiten | Wand | Installationswand | WI-IW | 0 | A | 7.5 | 1213HWa0812968248 | NEW | no | no | 0 | 0 | no | 0 | no | Codetext | AllplanAttributes - Ortscode_Geschoßbezeichnung: E02; W_Deckenanschluss: Gleitender Deckenanschluss Fall 03; ash_W_Trockenbau_Qualitäten: 2
 | H2 Ebene +2 | Installationsraum | 1213Wa 0812970762 | yes | Codetext | m² | Trockenbauarbeiten | Wand | Installationswand | Installationsraum | 0 | A | 7.5 | 1213HWa0812968248 | NEW | no | no | 0 | 0 | no | 0 | no | Codetext | AllplanAttributes - Ortscode_Geschoßbezeichnung: E02
 | H2 Ebene +2 | WI-IW | 1213Wa 0812970693 | yes | Codetext | m² | Trockenbauarbeiten | Wand | Installationswand | WI-IW | 0 | A | 7.5 | 1213HWa0812968250 | NEW | no | no | 0 | 0 | no | 47 | no | Codetext | AllplanAttributes - Ortscode_Geschoßbezeichnung: E02; W_Deckenanschluss: Gleitender Deckenanschluss Fall 03; ash_W_Trockenbau_Qualitäten: 11
 | H2 Ebene +2 | Installationsraum | 1213Wa 0812970695 | yes | Codetext | m² | Trockenbauarbeiten | Wand | Installationswand | Installationsraum | 0 | A | 7.5 | 1213HWa0812968250 | NEW | no | no | 0 | 0 | no | 0 | no | Codetext | AllplanAttributes - Ortscode_Geschoßbezeichnung: E02
 | H2 Ebene +2 | WI-IW | 1213Wa 0812970697 | yes | Codetext | m² | Trockenbauarbeiten | Wand | Installationswand | WI-IW | 0 | A | 7.5 | 1213HWa0812968250 | NEW | no | no | 0 | 0 | no | 47 | no | Codetext | AllplanAttributes - Ortscode_Geschoßbezeichnung: E02; W_Deckenanschluss: Gleitender Deckenanschluss Fall 03; ash_W_Trockenbau_Qualitäten: 11
 | H2 Ebene +2 | WI-IW | 1213Wa 0812970293 | yes | Codetext | m² | Trockenbauarbeiten | Wand | Installationswand | WI-IW | 0 | A | 7.5 | 1213HWa0812968248 | NEW | no | no | 0 | 0 | no | 0 | no | Codetext | AllplanAttributes - Ortscode_Geschoßbezeichnung: E02; W_Deckenanschluss: Gleitender Deckenanschluss Fall 03; ash_W_Trockenbau_Qualitäten: 2
 | H2 Ebene +2 | Installationsraum | 1213Wa 0812970760 | yes | Codetext | m² | Trockenbauarbeiten | Wand | Installationswand | Installationsraum | 0 | A | 7.5 | 1213HWa0812968248 | NEW | no | no | 0 | 0 | no | 0 | no | Codetext | AllplanAttributes - Ortscode_Geschoßbezeichnung: E02
 | H2 Ebene +2 | WI-IW | 1213Wa 0812970756 | yes | Codetext | m² | Trockenbauarbeiten | Wand | Installationswand | WI-IW | 0 | A | 7.5 | 1213HWa0812968248 | NEW | no | no | 0 | 0 | no | 0 | no | Codetext | AllplanAttributes - Ortscode_Geschoßbezeichnung: E02; W_Deckenanschluss: Gleitender Deckenanschluss Fall 03; ash_W_Trockenbau_Qualitäten: 2
 | H2 Ebene +2 | Installationsraum | 1213Wa 0812970297 | yes | Codetext | m² | Trockenbauarbeiten | Wand | Installationswand | Installationsraum | 0 | A | 7.5 | 1213HWa0812968248 | NEW | no | no | 0 | 0 | no | 0 | no | Codetext | AllplanAttributes - Ortscode_Geschoßbezeichnung: E02
 | H2 Ebene +2 | WI-IW | 1213Wa 0812970269 | yes | Codetext | m² | Trockenbauarbeiten | Wand | Installationswand | WI-IW | 0 | A | 7.5 | 1213HWa0812968250 | NEW | no | no | 0 | 0 | no | 47 | no | Codetext | AllplanAttributes - Ortscode_Geschoßbezeichnung: E02; W_Deckenanschluss: Gleitender Deckenanschluss Fall 03; ash_W_Trockenbau_Qualitäten: 11
 | H2 Ebene +2 | Installationsraum | 1213Wa 0812970702 | yes | Codetext | m² | Trockenbauarbeiten | Wand | Installationswand | Installationsraum | 0 | A | 7.5 | 1213HWa0812968250 | NEW | no | no | 0 | 0 | no | 0 | no | Codetext | AllplanAttributes - Ortscode_Geschoßbezeichnung: E02
 | H2 Ebene +2 | WI-IW | 1213Wa 0812970704 | yes | Codetext | m² | Trockenbauarbeiten | Wand | Installationswand | WI-IW | 0 | A | 7.5 | 1213HWa0812968250 | NEW | no | no | 0 | 0 | no | 47 | no | Codetext | AllplanAttributes - Ortscode_Geschoßbezeichnung: E02; W_Deckenanschluss: Gleitender Deckenanschluss Fall 03; ash_W_Trockenbau_Qualitäten: 11
 | H2 Ebene +2 | WI-IW | 1213Wa 0812970758 | yes | Codetext | m² | Trockenbauarbeiten | Wand | Installationswand | WI-IW | 0 | A | 7.5 | 1213HWa0812968248 | NEW | no | no | 0 | 0 | no | 0 | no | Codetext | AllplanAttributes - Ortscode_Geschoßbezeichnung: E02; W_Deckenanschluss: Gleitender Deckenanschluss Fall 03; ash_W_Trockenbau_Qualitäten: 2
 | H2 Ebene +2 | Installationsraum | 1213Wa 0812970295 | yes | Codetext | m² | Trockenbauarbeiten | Wand | Installationswand | Installationsraum | 0 | A | 7.5 | 1213HWa0812968248 | NEW | no | no | 0 | 0 | no | 0 | no | Codetext | AllplanAttributes - Ortscode_Geschoßbezeichnung: E02
 | H2 Ebene +2 | WI-IW | 1213Wa 0812970746 | yes | Codetext | m² | Trockenbauarbeiten | Wand | Installationswand | WI-IW | 0 | A | 7.5 | 1213HWa0812968194 | NEW | no | no | REI 30-A1 - D,s2-d0 +A1 | 0 | no |  | no | Codetext | AllplanAttributes - Ortscode_Geschoßbezeichnung: E02; W_Deckenanschluss: Gleitender Deckenanschluss Fall 01; ash_W_Trockenbau_Qualitäten: 11
 | H2 Ebene +2 | Installationsraum | 1213Wa 0812970744 | yes | Codetext | m² | Trockenbauarbeiten | Wand | Installationswand | Installationsraum | 0 | A | 7.5 | 1213HWa0812968194 | NEW | no | no | 0 | 0 | no | 0 | no | Codetext | AllplanAttributes - Ortscode_Geschoßbezeichnung: E02
 | H2 Ebene +2 | WI-IW | 1213Wa 0812970742 | yes | Codetext | m² | Trockenbauarbeiten | Wand | Installationswand | WI-IW | 0 | A | 7.5 | 1213HWa0812968194 | NEW | no | no | 0 | 0 | no |  | no | Codetext | AllplanAttributes - Ortscode_Geschoßbezeichnung: E02; W_Deckenanschluss: Gleitender Deckenanschluss Fall 01; ash_W_Trockenbau_Qualitäten: 11
 | H2 Ebene +2 | WI-LB | 1213Wa 0812986117 | yes | Codetext | m² | Trockenbauarbeiten | Wand | Innenwand 1-Schalig | WI-LB | 0 | A | 7.5 | 1213HWa0812968185 | NEW | no | no | REI 30-A1 - D,s2-d0 +A1 | 0 | no | 0 | no | Codetext | AllplanAttributes - Ortscode_Geschoßbezeichnung: E02; ash_W_Trockenbau_Qualitäten: 16
 | H2 Ebene +2 | WI-HW 60 | 1213Wa 0813078469 | yes | Codetext | m² | Zimmer- und Holzbauarbeiten | Wand | Innenwand 1-Schalig | WI-HW 60 | 0 | A | 7.5 | 1213HWa0812968185 | NEW | no | no | REI 30-A1 - D,s2-d0 +A1 | 0 | no | 0 | no | Codetext | AllplanAttributes - Ortscode_Geschoßbezeichnung: E02; ash W_laufende Nr. Statik: 3 (W 3.0)
 | H2 Ebene +2 | WI-LB | 1213Wa 0813688372 | yes | Codetext | m² | Trockenbauarbeiten | Wand | Innenwand 1-Schalig | WI-LB | 0 | A | 7.5 | 1213HWa0812968185 | NEW | no | no | REI 30-A1 - D,s2-d0 +A1 | 0 | no | 0 | no | Codetext | AllplanAttributes - Ortscode_Geschoßbezeichnung: E02; ash_W_Trockenbau_Qualitäten: 16
 | H2 Ebene +2 | WI-HW 60 | 1213Wa 0813688370 | yes | Codetext | m² | Zimmer- und Holzbauarbeiten | Wand | Innenwand 1-Schalig | WI-HW 60 | 0 | A | 7.5 | 1213HWa0812968185 | NEW | no | no | REI 30-A1 - D,s2-d0 +A1 | 0 | no | 0 | no | Codetext | AllplanAttributes - Ortscode_Geschoßbezeichnung: E02; ash W_laufende Nr. Statik: 3 (W 3.0)
 | H2 Ebene +2 | WI-HW 60 | 1213Wa 0813688546 | yes | Codetext | m² | Zimmer- und Holzbauarbeiten | Wand | Innenwand 1-Schalig | WI-HW 60 | 0 | A | 7.5 | 1213HWa0812968185 | NEW |  | no | REI 30-A1 - D,s2-d0 +A1 | 0 | no | 0 | no | Codetext | AllplanAttributes - Ortscode_Geschoßbezeichnung: E02; ash W_laufende Nr. Statik: 3 (W 3.0)
 | H2 Ebene +2 | Installationsraum | 1213Wa 0812970277 | yes | Codetext | m² | Trockenbauarbeiten | Wand | Installationswand | Installationsraum | 0 | A | 7.5 | 1213HWa0812968324 | NEW | no | no | 0 | 0 | no | 0 | no | Codetext | AllplanAttributes - Ortscode_Geschoßbezeichnung: E02
 | H2 Ebene +2 | WI-IW | 1213Wa 0812970279 | yes | Codetext | m² | Trockenbauarbeiten | Wand | Installationswand | WI-IW | 0 | A | 7.5 | 1213HWa0812968324 | NEW | no | no | 0 | 0 | no |  | no | Codetext | AllplanAttributes - Ortscode_Geschoßbezeichnung: E02; W_Deckenanschluss: Gleitender Deckenanschluss Fall 01; ash_W_Trockenbau_Qualitäten: 2
 | H2 Ebene +2 | Installationsraum | 1213Wa 0812970281 | yes | Codetext | m² | Trockenbauarbeiten | Wand | Installationswand | Installationsraum | 0 | A | 7.5 | 1213HWa0812968329 | NEW |  | no | 0 | 0 | no | 0 | no | Codetext | AllplanAttributes - Ortscode_Geschoßbezeichnung: E02
 | H2 Ebene +2 | WI-VS | 1213Wa 0812970283 | yes | Codetext | m² | Trockenbauarbeiten | Wand | Installationswand | WI-VS | 0 | A | 7.5 | 1213HWa0812968329 | NEW |  | no | 0 | 0 | no | 0 | no | Codetext | AllplanAttributes - Ortscode_Geschoßbezeichnung: E02; W_Deckenanschluss: Gleitender Deckenanschluss Fall 01; ash_W_Trockenbau_Qualitäten: 2
 | H2 Ebene +2 | WI-IW | 1213Wa 0812970255 | yes | Codetext | m² | Trockenbauarbeiten | Wand | Installationswand | WI-IW | 0 | A | 7.5 | 1213HWa0812968335 | NEW | no | no | 0 | 0 | no | 0 | no | Codetext | AllplanAttributes - Ortscode_Geschoßbezeichnung: E02; W_Deckenanschluss: Gleitender Deckenanschluss Fall 01; ash_W_Trockenbau_Qualitäten: 11
 | H2 Ebene +2 | Installationsraum | 1213Wa 0812970253 | yes | Codetext | m² | Trockenbauarbeiten | Wand | Installationswand | Installationsraum | 0 | A | 7.5 | 1213HWa0812968335 | NEW | no | no | 0 | 0 | no | 0 | no | Codetext | AllplanAttributes - Ortscode_Geschoßbezeichnung: E02
 | H2 Ebene +2 | WI-IW | 1213Wa 0812970251 | yes | Codetext | m² | Trockenbauarbeiten | Wand | Installationswand | WI-IW | 0 | A | 7.5 | 1213HWa0812968335 | NEW | no | no | 0 | 0 | no | 0 | no | Codetext | AllplanAttributes - Ortscode_Geschoßbezeichnung: E02; W_Deckenanschluss: Gleitender Deckenanschluss Fall 01; ash_W_Trockenbau_Qualitäten: 11
 | H2 Ebene +2 | WI-LB | 1213Wa 0813568608 | yes | Codetext | m² | Trockenbauarbeiten | Wand | Innenwand 1-Schalig | WI-LB | 0 | A | 7.5 | 1213HWa0812968339 | NEW | no | no | REI 30-A1 - D,s2-d0 +A1 | 0 | no | 47 | no | Codetext | AllplanAttributes - Ortscode_Geschoßbezeichnung: E02; W_Deckenanschluss: Gleitender Deckenanschluss Fall 01; ash_W_Trockenbau_Qualitäten: 1a
 | H2 Ebene +2 | WI-LB | 1213Wa 0812986099 | yes | Codetext | m² | Trockenbauarbeiten | Wand | Innenwand 1-Schalig | WI-LB | 0 | A | 7.5 | 1213HWa0812968323 | NEW | no | no | 0 | 0 | no | 0 | no | Codetext | AllplanAttributes - Ortscode_Geschoßbezeichnung: E02; W_Deckenanschluss: Gleitender Deckenanschluss Fall 01; ash_W_Trockenbau_Qualitäten: 12b
 | H2 Ebene +2 | WI-LB | 1213Wa 0813689091 | yes | Codetext | m² | Trockenbauarbeiten | Wand | Innenwand 1-Schalig | WI-LB | 0 | A | 7.5 | 1213HWa0812968059 | NEW |  | no | REI 60-A1 - D,s2-d0 +A1 | 0 | no | 0 | no | Codetext | AllplanAttributes - Ortscode_Geschoßbezeichnung: E02; W_Deckenanschluss: Gleitender Deckenanschluss Fall 01; ash_W_Trockenbau_Qualitäten: 1b
 | H2 Ebene +2 | WI-LB | 1213Wa 0813689108 | yes | Codetext | m² | Trockenbauarbeiten | Wand | Innenwand 1-Schalig | WI-LB | 0 | A | 7.5 | 1213HWa0812968339 | NEW | no | no | REI 30-A1 - D,s2-d0 +A1 | 0 | no | 47 | no | Codetext | AllplanAttributes - Ortscode_Geschoßbezeichnung: E02; W_Deckenanschluss: Gleitender Deckenanschluss Fall 01; ash_W_Trockenbau_Qualitäten: 1b
 | H2 Ebene +2 | WI-LB | 1213Wa 0813689120 | yes | Codetext | m² | Trockenbauarbeiten | Wand | Innenwand 1-Schalig | WI-LB | 0 | A | 7.5 | 1213HWa0812968339 | NEW | no | no | REI 30-A1 - D,s2-d0 +A1 | 0 | no | 47 | no | Codetext | AllplanAttributes - Ortscode_Geschoßbezeichnung: E02; W_Deckenanschluss: Gleitender Deckenanschluss Fall 01; ash_W_Trockenbau_Qualitäten: 1b
 | H2 Ebene +2 | WI-LB | 1213Wa 0813689125 | yes | Codetext | m² | Trockenbauarbeiten | Wand | Innenwand 1-Schalig | WI-LB | 0 | A | 7.5 | 1213HWa0812968339 | NEW | no | no | REI 30-A1 - D,s2-d0 +A1 | 0 | no | 47 | no | Codetext | AllplanAttributes - Ortscode_Geschoßbezeichnung: E02; W_Deckenanschluss: Gleitender Deckenanschluss Fall 01; ash_W_Trockenbau_Qualitäten: 1b
 | H2 Ebene +2 | WI-LB | 1213Wa 0813689428 | yes | Codetext | m² | Trockenbauarbeiten | Wand | Innenwand 1-Schalig | WI-LB | 0 | A | 7.5 | 1213HWa0812968081 | NEW |  | no | 0 | 0 | no | 0 | no | Codetext | AllplanAttributes - Ortscode_Geschoßbezeichnung: E02; ash D_Detailverweis: FL1; ash D_Plannummer: 1680; W_Deckenanschluss: Gleitender Deckenanschluss Fall 01
 | H2 Ebene +2 | WI-LB | 1213Wa 0813689447 | yes | Codetext | m² | Trockenbauarbeiten | Wand | Innenwand 1-Schalig | WI-LB | 0 | A | 7.5 | 1213HWa0812968081 | NEW | no | no | 0 | 0 | no | 0 | no | Codetext | AllplanAttributes - Ortscode_Geschoßbezeichnung: E02; W_Deckenanschluss: Gleitender Deckenanschluss Fall 01; ash_W_Trockenbau_Qualitäten: 1b
 | H2 Ebene +2 | Installationsraum | 1213Wa 0812970727 | yes | Codetext | m² | Trockenbauarbeiten | Wand | Installationswand | Installationsraum | 0 | A | 7.5 | 1213HWa0812968337 | NEW |  | no | 0 | 0 | no | 0 | no | Codetext | AllplanAttributes - Ortscode_Geschoßbezeichnung: E02
 | H2 Ebene +2 | WI-VS | 1213Wa 0812970729 | yes | Codetext | m² | Trockenbauarbeiten | Wand | Installationswand | WI-VS | 0 | A | 7.5 | 1213HWa0812968337 | NEW |  | no | 0 | 0 | no | 0 | no | Codetext | AllplanAttributes - Ortscode_Geschoßbezeichnung: E02; W_Deckenanschluss: Gleitender Deckenanschluss Fall 01; ash_W_Trockenbau_Qualitäten: 18
 | H2 Ebene +2 | WI-VS | 1213Wa 0813025637 | yes | Codetext | m² | Trockenbauarbeiten | Wand | Installationswand | WI-VS | 0 | A | 7.5 | 1213HWa0813025636 | NEW |  | no | 0 | 0 | no | 0 | no | Codetext | AllplanAttributes - Ortscode_Geschoßbezeichnung: E02; W_Deckenanschluss: Gleitender Deckenanschluss Fall 01; ash_W_Trockenbau_Qualitäten: 18
 | H2 Ebene +2 | WI-IW | 1213Wa 0812970430 | yes | Codetext | m² | Trockenbauarbeiten | Wand | Installationswand | WI-IW | 0 | A | 7.5 | 1213HWa0812968430 | NEW |  | no | 0 | 0 | no | 0 | no | Codetext | AllplanAttributes - Ortscode_Geschoßbezeichnung: E02; W_Deckenanschluss: Gleitender Deckenanschluss Fall 01; ash_W_Trockenbau_Qualitäten: 18
 | H2 Ebene +2 | Installationsraum | 1213Wa 0812970424 | yes | Codetext | m² | Trockenbauarbeiten | Wand | Installationswand | Installationsraum | 0 | A | 7.5 | 1213HWa0812968430 | NEW |  | no | 0 | 0 | no | 0 | no | Codetext | AllplanAttributes - Ortscode_Geschoßbezeichnung: E02
 | H2 Ebene +2 | WI-STB | 1213Wa 0812970426 | yes | Codetext | m² | Zimmer- und Holzbauarbeiten | Wand | Außenwand 1-Schalig | WI-STB | 0 | A | 7.5 | 1213HWa0812968474 | NEW | yes | no | REI 60-A1 - D,s2-d0 /A1 | 0 | no | 52 | no | Codetext | AllplanAttributes - Ortscode_Geschoßbezeichnung: E02
 | H2 Ebene +2 | WI-LB | 1213Wa 0812970442 | yes | Codetext | m² | Trockenbauarbeiten | Wand | Außenwand 1-Schalig | WI-LB | 0 | A | 7.5 | 1213HWa0812968474 | NEW | no | no | REI 60-A1 - D,s2-d0 /A1 | 0 | no |  | no | Codetext | AllplanAttributes - Ortscode_Geschoßbezeichnung: E02; ash_W_Trockenbau_Qualitäten: 9
 | H2 Ebene +2 | WI-LB | 1213Wa 0812970437 | yes | Codetext | m² | Trockenbauarbeiten | Wand | Innenwand 1-Schalig | WI-LB | 0 | A | 7.5 | 1213HWa0812968477 | NEW | no | no | REI 60-A1 - D,s2-d0 /A1 | 0 | no |  | no | Codetext | AllplanAttributes - Ortscode_Geschoßbezeichnung: E02; ash_W_Trockenbau_Qualitäten: 9
 | H2 Ebene +2 | WI-STB | 1213Wa 0812970439 | yes | Codetext | m² | Zimmer- und Holzbauarbeiten | Wand | Außenwand 1-Schalig | WI-STB | 0 | A | 7.5 | 1213HWa0812968476 | NEW |  | no | REI 60-A1 - D,s2-d0 /A1 | 0 | no | 52 | no | Codetext | AllplanAttributes - Ortscode_Geschoßbezeichnung: E02
 | H2 Ebene +2 | Installationsraum | 1213Wa 0812970432 | yes | Codetext | m² | Trockenbauarbeiten | Wand | Außenwand 1-Schalig | Installationsraum | 0 | A | 7.5 | 1213HWa0812968430 | NEW |  | no | 0 | 0 | no | 0 | no | Codetext | AllplanAttributes - Ortscode_Geschoßbezeichnung: E02
 | H2 Ebene +2 | WI-LB | 1213Wa 0813689683 | yes | Codetext | m² | Trockenbauarbeiten | Wand | Außenwand 1-Schalig | WI-LB | 0 | A | 7.5 | 1213HWa0812968476 | NEW |  | no | REI 60-A1 - D,s2-d0 /A1 | 0 | no |  | no | Codetext | AllplanAttributes - Ortscode_Geschoßbezeichnung: E02; ash_W_Trockenbau_Qualitäten: 16
 | H2 Ebene +2 | WI-LB | 1213Wa 0813689907 | yes | Codetext | m² | Trockenbauarbeiten | Wand | Innenwand 1-Schalig | WI-LB | 0 | A | 7.5 | 1213HWa0812968472 | NEW | no | no | REI 60-A1 - D,s2-d0 /A1 | 0 | no | 0 | no | Codetext | AllplanAttributes - Ortscode_Geschoßbezeichnung: E02; ash_W_Trockenbau_Qualitäten: 9
 | H2 Ebene +2 | WI-LB | 1213Wa 0813689915 | yes | Codetext | m² | Trockenbauarbeiten | Wand | Innenwand 1-Schalig | WI-LB | 0 | A | 7.5 | 1213HWa0812968472 | NEW | no | no | REI 60-A1 - D,s2-d0 /A1 | 0 | no | 0 | no | Codetext | AllplanAttributes - Ortscode_Geschoßbezeichnung: E02; ash_W_Trockenbau_Qualitäten: 9
 | H2 Ebene +2 | Installationsraum | 1213Wa 0812971195 | yes | Codetext | m² | Trockenbauarbeiten | Wand | Installationswand | Installationsraum | 0 | A | 7.5 | 1213HWa0812971181 | NEW | no | no | 0 | 0 | no | 0 | no | Codetext | AllplanAttributes - Ortscode_Geschoßbezeichnung: E02
 | H2 Ebene +2 | WI-VS | 1213Wa 0812971193 | yes | Codetext | m² | Trockenbauarbeiten | Wand | Installationswand | WI-VS | 0 | A | 7.5 | 1213HWa0812971181 | NEW | no | no | 0 | 0 | no | 0 | no | Codetext | AllplanAttributes - Ortscode_Geschoßbezeichnung: E02; W_Deckenanschluss: Gleitender Deckenanschluss Fall 01; ash_W_Trockenbau_Qualitäten: 2
 | H2 Ebene +2 | Installationsraum | 1213Wa 0812971199 | yes | Codetext | m² | Trockenbauarbeiten | Wand | Installationswand | Installationsraum | 0 | A | 7.5 | 1213HWa0812969834 | NEW | no | no | 0 | 0 | no | 0 | no | Codetext | AllplanAttributes - Ortscode_Geschoßbezeichnung: E02
 | H2 Ebene +2 | WI-VS | 1213Wa 0812971197 | yes | Codetext | m² | Trockenbauarbeiten | Wand | Installationswand | WI-VS | 0 | A | 7.5 | 1213HWa0812969834 | NEW | no | no | 0 | 0 | no | 0 | no | Codetext | AllplanAttributes - Ortscode_Geschoßbezeichnung: E02; W_Deckenanschluss: Gleitender Deckenanschluss Fall 01; ash_W_Trockenbau_Qualitäten: 2
 | H2 Ebene +2 | WI-STB | 1213Wa 0812971172 | yes | Codetext | m² | Zimmer- und Holzbauarbeiten | Wand | Innenwand 1-Schalig | WI-STB | 0 | A | 7.5 | 1213HWa0812968429 | NEW | no | no | REI 60-A1 - D,s2-d0 /A1 | 0 | no | 42 | no | Codetext | AllplanAttributes - Ortscode_Geschoßbezeichnung: E02
 | H2 Ebene +2 | WI-LB | 1213Wa 0813690794 | yes | Codetext | m² | Trockenbauarbeiten | Wand | Innenwand 1-Schalig | WI-LB | 0 | A | 7.5 | 1213HWa0812968154 | NEW | no | no | REI 60-A1 - D,s2-d0 /A1 | 0 | no |  | no | Codetext | AllplanAttributes - Ortscode_Geschoßbezeichnung: E02; ash_W_Trockenbau_Qualitäten: 9
 | H2 Ebene +2 | WI-STB | 1213Wa 0812986389 | yes | Codetext | m² | Zimmer- und Holzbauarbeiten | Wand | Innenwand 1-Schalig | WI-STB | 0 | A | 7.5 | 1213HWa0812969878 | NEW | no | no | REI 60-A1 - D,s2-d0 /A1 | 0 | no | 0 | no | Codetext | AllplanAttributes - Ortscode_Geschoßbezeichnung: E02
 | H2 Ebene +2 | WI-LB | 1213Wa 0813690449 | yes | Codetext | m² | Trockenbauarbeiten | Wand | Innenwand 1-Schalig | WI-LB | 0 | A | 7.5 | 1213HWa0812968154 | NEW | no | no | REI 60-A1 - D,s2-d0 /A1 | 0 | no | 0 | no | Codetext | AllplanAttributes - Ortscode_Geschoßbezeichnung: E02; ash_W_Trockenbau_Qualitäten: 9
 | H2 Ebene +2 | WI-STB | 1213Wa 0812986384 | yes | Codetext | m² | Zimmer- und Holzbauarbeiten | Wand | Innenwand 1-Schalig | WI-STB | 0 | A | 7.5 | 1213HWa0812968509 | NEW | yes | no | REI 60-A1 - D,s2-d0 /A1 | 0 | no | 0 | no | Codetext | AllplanAttributes - Ortscode_Geschoßbezeichnung: E02
 | H2 Ebene +2 | WI-LB | 1213Wa 0813496622 | yes | Codetext | m² | Trockenbauarbeiten | Wand | Innenwand 1-Schalig | WI-LB | 0 | A | 7.5 | 1213HWa0812968154 | NEW | no | no | REI 60-A1 - D,s2-d0 /A1 | 0 | no | 0 | no | Codetext | AllplanAttributes - Ortscode_Geschoßbezeichnung: E02; ash_W_Trockenbau_Qualitäten: 9
 | H2 Ebene +2 | WI-LW 60 | 1213Wa 0812986403 | yes | Codetext | m² | Trockenbauarbeiten | Wand | Innenwand 1-Schalig | WI-LW 60 | 0 | A | 7.5 | 1213HWa0812968555 | NEW | yes | no | REI 60-A1 - D,s2-d0 +A1 | 0 | no | 0 | no | Codetext | AllplanAttributes - Ortscode_Geschoßbezeichnung: E02; W_Deckenanschluss: Gleitender Deckenanschluss Fall 01; ash_W_Trockenbau_Qualitäten: 12b
im Zusammenhang mit der Möblierung anzufertigen | H2 Ebene +2 | WI-LB | 1213Wa 0813692118 | yes | Codetext | m² | Trockenbauarbeiten | Wand | im Zusammenhang mit der Möblierung anzufertigen | WI-LB | 0 | A | 7.5 |  | NEW | no | no | 0 | 0 | no | 47 | no | Codetext | AllplanAttributes - Ortscode_Geschoßbezeichnung: E02; W_Deckenanschluss: Gleitender Deckenanschluss Fall 01; ash_W_Trockenbau_Qualitäten: 1a
im Zusammenhang mit der Möblierung anzufertigen | H2 Ebene +2 | WI-LB | 1213Wa 0813692128 | yes | Codetext | m² | Trockenbauarbeiten | Wand | im Zusammenhang mit der Möblierung anzufertigen | WI-LB | 0 | A | 7.5 |  | NEW | no | no | 0 | 0 | no | 47 | no | Codetext | AllplanAttributes - Ortscode_Geschoßbezeichnung: E02; W_Deckenanschluss: Gleitender Deckenanschluss Fall 01; ash_W_Trockenbau_Qualitäten: 8
im Zusammenhang mit der Möblierung anzufertigen | H2 Ebene +2 | WI-LB | 1213Wa 0813692236 | yes | Codetext | m² | Trockenbauarbeiten | Wand | im Zusammenhang mit der Möblierung anzufertigen | WI-LB | 0 | A | 7.5 |  | NEW | no | no | 0 | 0 | no | 47 | no | Codetext | AllplanAttributes - Ortscode_Geschoßbezeichnung: E02; W_Deckenanschluss: Gleitender Deckenanschluss Fall 01; ash_W_Trockenbau_Qualitäten: 8
im Zusammenhang mit der Möblierung anzufertigen | H2 Ebene +2 | WI-LB | 1213Wa 0813692246 | yes | Codetext | m² | Trockenbauarbeiten | Wand | im Zusammenhang mit der Möblierung anzufertigen | WI-LB | 0 | A | 7.5 |  | NEW | no | no | 0 | 0 | no | 47 | no | Codetext | AllplanAttributes - Ortscode_Geschoßbezeichnung: E02; W_Deckenanschluss: Gleitender Deckenanschluss Fall 01; ash_W_Trockenbau_Qualitäten: 8
im Zusammenhang mit der Möblierung anzufertigen | H2 Ebene +2 | WI-LB | 1213Wa 0813692753 | yes | Codetext | m² | Trockenbauarbeiten | Wand | im Zusammenhang mit der Möblierung anzufertigen | WI-LB | 0 | A | 7.5 |  | NEW | no | no | 0 | 0 | no | 0 | no | Codetext | AllplanAttributes - Ortscode_Geschoßbezeichnung: E02; W_Deckenanschluss: Gleitender Deckenanschluss Fall 01; ash_W_Trockenbau_Qualitäten: 18
im Zusammenhang mit der Möblierung anzufertigen | H2 Ebene +2 | WI-LB | 1213Wa 0813692729 | yes | Codetext | m² | Trockenbauarbeiten | Wand | im Zusammenhang mit der Möblierung anzufertigen | WI-LB | 0 | A | 7.5 |  | NEW | no | no | 0 | 0 | no | 0 | no | Codetext | AllplanAttributes - Ortscode_Geschoßbezeichnung: E02; W_Deckenanschluss: Gleitender Deckenanschluss Fall 01; ash_W_Trockenbau_Qualitäten: 18
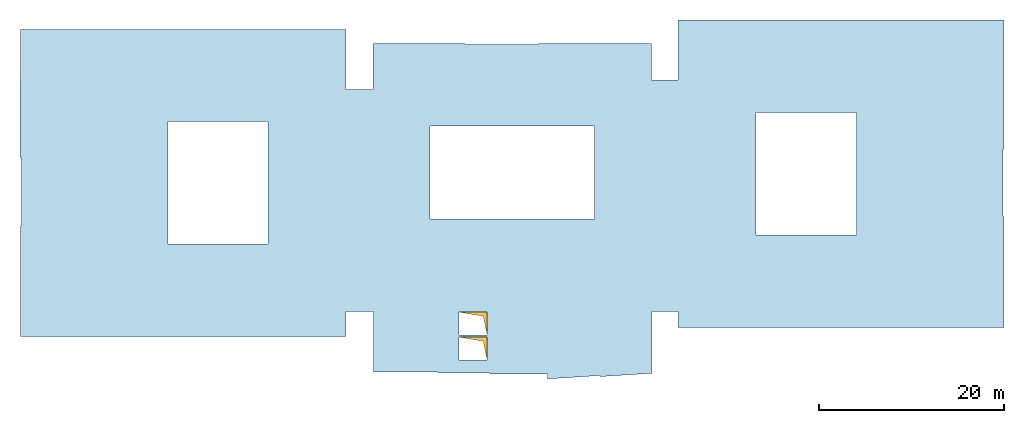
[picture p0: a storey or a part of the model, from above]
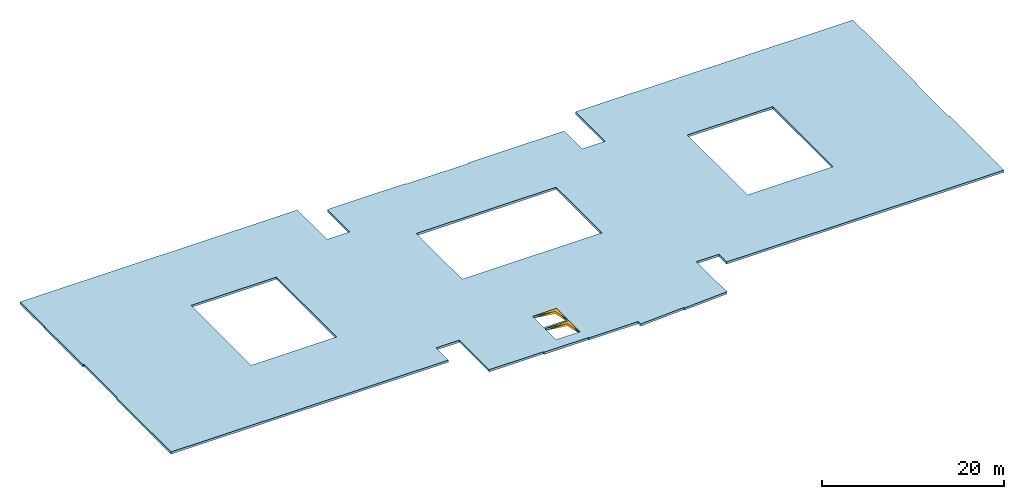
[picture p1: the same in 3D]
Properties of the parts of a building model (IFC4), part 58 of 80

# IfcWall (6826)
Name | In | Material | Allright_Bauteil_ID | 2D Interaktion | Codetext | Abrechnungsart | Gewerk | Objektname | Bezeichnung | AllplanAttributes, Material | Typ = SurfaceSpreadOfFlame | Brandschutzklasse | OKFF | P_ID | Status | LoadBearing | IsExternal | FireRating | ThermalTransmittance (W/K/m2) | Combustible | AcousticRating | Compartmentation | Reference
im Zusammenhang mit der Möblierung anzufertigen | H2 Ebene +2 | WI-LB | 1213Wa 0813692736 | yes | Codetext | m² | Trockenbauarbeiten | Wand | im Zusammenhang mit der Möblierung anzufertigen | WI-LB | 0 | A | 7.5 |  | NEW | no | no | 0 | 0 | no | 0 | no | Codetext | AllplanAttributes - Ortscode_Geschoßbezeichnung: E02; W_Deckenanschluss: Gleitender Deckenanschluss Fall 01; ash_W_Trockenbau_Qualitäten: 18
im Zusammenhang mit der Möblierung anzufertigen | H2 Ebene +2 | WI-LB | 1213Wa 0813693314 | yes | Codetext | m² | Trockenbauarbeiten | Wand | im Zusammenhang mit der Möblierung anzufertigen | WI-LB | 0 | A | 7.5 |  | NEW | no | no | 0 | 0 | no | 0 | no | Codetext | AllplanAttributes - Ortscode_Geschoßbezeichnung: E02; W_Deckenanschluss: Gleitender Deckenanschluss Fall 01; ash_W_Trockenbau_Qualitäten: 18
im Zusammenhang mit der Möblierung anzufertigen | H2 Ebene +2 | WI-LB | 1213Wa 0813693322 | yes | Codetext | m² | Trockenbauarbeiten | Wand | im Zusammenhang mit der Möblierung anzufertigen | WI-LB | 0 | A | 7.5 |  | NEW | no | no | 0 | 0 | no | 0 | no | Codetext | AllplanAttributes - Ortscode_Geschoßbezeichnung: E02; W_Deckenanschluss: Gleitender Deckenanschluss Fall 01; ash_W_Trockenbau_Qualitäten: 18
im Zusammenhang mit der Möblierung anzufertigen | H2 Ebene +2 | WI-LB | 1213Wa 0813693333 | yes | Codetext | m² | Trockenbauarbeiten | Wand | im Zusammenhang mit der Möblierung anzufertigen | WI-LB | 0 | A | 7.5 |  | NEW | no | no | 0 | 0 | no | 0 | no | Codetext | AllplanAttributes - Ortscode_Geschoßbezeichnung: E02; W_Deckenanschluss: Gleitender Deckenanschluss Fall 01; ash_W_Trockenbau_Qualitäten: 18
im Zusammenhang mit der Möblierung anzufertigen | H2 Ebene +2 | WI-LB | 1213Wa 0813693344 | yes | Codetext | m² | Trockenbauarbeiten | Wand | im Zusammenhang mit der Möblierung anzufertigen | WI-LB | 0 | A | 7.5 |  | NEW | no | no | 0 | 0 | no | 0 | no | Codetext | AllplanAttributes - Ortscode_Geschoßbezeichnung: E02; W_Deckenanschluss: Gleitender Deckenanschluss Fall 01; ash_W_Trockenbau_Qualitäten: 18
im Zusammenhang mit der Möblierung anzufertigen | H2 Ebene +2 | WI-LB | 1213Wa 0813693376 | yes | Codetext | m² | Trockenbauarbeiten | Wand | im Zusammenhang mit der Möblierung anzufertigen | WI-LB | 0 | A | 7.5 |  | NEW | no | no | 0 | 0 | no | 0 | no | Codetext | AllplanAttributes - Ortscode_Geschoßbezeichnung: E02; W_Deckenanschluss: Gleitender Deckenanschluss Fall 01; ash_W_Trockenbau_Qualitäten: 18
 | H2 Ebene +2 | WI-HW 60 | 1213Wa 0813693727 | yes | Codetext | m² | Zimmer- und Holzbauarbeiten | Wand | Innenwand 1-Schalig | WI-HW 60 | 0 | A | 7.5 | 1213HWa0812968158 | NEW |  | no | REI 60-A1 - D,s2-d0 +A1 | 0 | no | 52 | no | Codetext | AllplanAttributes - Ortscode_Geschoßbezeichnung: E02; Sicherheitsklasse: -; ash W_laufende Nr. Statik: 3 (W 3.0)
im Zusammenhang mit der Möblierung anzufertigen | H2 Ebene +2 | WI-LB | 1213Wa 0813694037 | yes | Codetext | m² | Trockenbauarbeiten | Wand | im Zusammenhang mit der Möblierung anzufertigen | WI-LB | 0 | A | 7.5 |  | NEW | no | no | 0 | 0 | no | 47 | no | Codetext | AllplanAttributes - Ortscode_Geschoßbezeichnung: E02; W_Deckenanschluss: Gleitender Deckenanschluss Fall 01; ash_W_Trockenbau_Qualitäten: 18
im Zusammenhang mit der Möblierung anzufertigen | H2 Ebene +2 | WI-LB | 1213Wa 0813694050 | yes | Codetext | m² | Trockenbauarbeiten | Wand | im Zusammenhang mit der Möblierung anzufertigen | WI-LB | 0 | A | 7.5 |  | NEW | no | no | 0 | 0 | no | 47 | no | Codetext | AllplanAttributes - Ortscode_Geschoßbezeichnung: E02; W_Deckenanschluss: Gleitender Deckenanschluss Fall 01; ash_W_Trockenbau_Qualitäten: 1a
im Zusammenhang mit der Möblierung anzufertigen | H2 Ebene +2 | WI-LB | 1213Wa 0813694355 | yes | Codetext | m² | Trockenbauarbeiten | Wand | im Zusammenhang mit der Möblierung anzufertigen | WI-LB | 0 | A | 7.5 |  | NEW | no | no | 0 | 0 | no | 47 | no | Codetext | AllplanAttributes - Ortscode_Geschoßbezeichnung: E02; W_Deckenanschluss: Gleitender Deckenanschluss Fall 01; ash_W_Trockenbau_Qualitäten: 18
 | H2 Ebene +2 | WI-LB | 1213Wa 0813198810 | yes | Codetext | m² | Trockenbauarbeiten | Wand | Innenwand 1-Schalig | WI-LB | 0 | A | 7.5 | 1163HWa0814107885 | NEW |  | no | 0 | 0 | no | 47 | no | Codetext | AllplanAttributes - Ortscode_Geschoßbezeichnung: E02; W_Deckenanschluss: Gleitender Deckenanschluss Fall 01; ash_W_Trockenbau_Qualitäten: 1d
 | H2 Ebene +2 | WI-PR | 1213Wa 0813694651 | yes | Codetext | m² | Trockenbauarbeiten | Wand | "BS-Beplankung; 2-fach Gipsfaserplatten" | WI-PR | 0 | A | 7.5 | 1163HWa0812836365 | NEW |  | no |  | 0 | no | 0 | no | Codetext | AllplanAttributes - Ortscode_Geschoßbezeichnung: E02; Positionsnummer_Text: U100
 | H2 Ebene +2 | WI-PR | 1213Wa 0813694648 | yes | Codetext | m² | Trockenbauarbeiten | Wand | "BS-Beplankung; 2-fach Gipsfaserplatten" | WI-PR | 0 | A | 7.5 | 1163HWa0812836365 | NEW |  | no |  | 0 | no | 0 | no | Codetext | AllplanAttributes - Ortscode_Geschoßbezeichnung: E02; Positionsnummer_Text: U100
 | H2 Ebene +2 | WI-PR | 1213Wa 0813694649 | yes | Codetext | m² | Trockenbauarbeiten | Wand | "BS-Beplankung; 2-fach Gipsfaserplatten" | WI-PR | 0 | A | 7.5 | 1163HWa0812836365 | NEW |  | no |  | 0 | no | 0 | no | Codetext | AllplanAttributes - Ortscode_Geschoßbezeichnung: E02; Positionsnummer_Text: U100
 | H2 Ebene +2 | WI-PR | 1213Wa 0813694650 | yes | Codetext | m² | Trockenbauarbeiten | Wand | "BS-Beplankung; 2-fach Gipsfaserplatten" | WI-PR | 0 | A | 7.5 | 1163HWa0812836365 | NEW |  | no |  | 0 | no | 0 | no | Codetext | AllplanAttributes - Ortscode_Geschoßbezeichnung: E02; Positionsnummer_Text: U100
 | H2 Ebene +2 | WI-PR | 1213Wa 0813694626 | yes | Codetext | m² | Trockenbauarbeiten | Wand | "BS-Beplankung; 2-fach Gipsfaserplatten" | WI-PR | 0 | A | 7.5 | 1163HWa0812836365 | NEW |  | no |  | 0 | no | 0 | no | Codetext | AllplanAttributes - Ortscode_Geschoßbezeichnung: E02; Positionsnummer_Text: U100
 | H2 Ebene +2 | WI-PR | 1213Wa 0813694631 | yes | Codetext | m² | Trockenbauarbeiten | Wand | "BS-Beplankung; 2-fach Gipsfaserplatten" | WI-PR | 0 | A | 7.5 | 1163HWa0812836365 | NEW |  | no |  | 0 | no | 0 | no | Codetext | AllplanAttributes - Ortscode_Geschoßbezeichnung: E02; Positionsnummer_Text: U100
 | H2 Ebene +2 | WI-PR | 1213Wa 0813694629 | yes | Codetext | m² | Trockenbauarbeiten | Wand | "BS-Beplankung; 2-fach Gipsfaserplatten" | WI-PR | 0 | A | 7.5 | 1163HWa0812836365 | NEW |  | no |  | 0 | no | 0 | no | Codetext | AllplanAttributes - Ortscode_Geschoßbezeichnung: E02; Positionsnummer_Text: U100
 | H2 Ebene +2 | WI-PR | 1213Wa 0813694628 | yes | Codetext | m² | Trockenbauarbeiten | Wand | "BS-Beplankung; 2-fach Gipsfaserplatten" | WI-PR | 0 | A | 7.5 | 1163HWa0812836365 | NEW |  | no |  | 0 | no | 0 | no | Codetext | AllplanAttributes - Ortscode_Geschoßbezeichnung: E02; Positionsnummer_Text: U100
im Zusammenhang mit der Möblierung anzufertigen | H2 Ebene +2 | WI-RIR | 1213Wa 0813446024 | yes | Codetext | m² | Tischlerarbeiten | Wand | im Zusammenhang mit der Möblierung anzufertigen | WI-RIR | 0 | A | 7.5 |  | NEW | no | no | 0 | 0 | no | 47 | no | Codetext | AllplanAttributes - Ortscode_Geschoßbezeichnung: E02; W_Deckenanschluss: Gleitender Deckenanschluss Fall 01; ash_W_Trockenbau_Qualitäten: 1b
 | H2 Ebene +2 | WI-PR | 1213Wa 0813694847 | yes | Codetext | m² | Trockenbauarbeiten | Wand | "BS-Beplankung; 2-fach Gipsfaserplatten" | WI-PR | 0 | A | 7.5 | 1163HWa0812836365 | NEW |  | no |  | 0 | no | 0 | no | Codetext | AllplanAttributes - Ortscode_Geschoßbezeichnung: E02; Positionsnummer_Text: U100
 | H2 Ebene +2 | WI-PR | 1213Wa 0813694844 | yes | Codetext | m² | Trockenbauarbeiten | Wand | "BS-Beplankung; 2-fach Gipsfaserplatten" | WI-PR | 0 | A | 7.5 | 1163HWa0812836365 | NEW |  | no |  | 0 | no | 0 | no | Codetext | AllplanAttributes - Ortscode_Geschoßbezeichnung: E02; Positionsnummer_Text: U100
 | H2 Ebene +2 | WI-PR | 1213Wa 0813694845 | yes | Codetext | m² | Trockenbauarbeiten | Wand | "BS-Beplankung; 2-fach Gipsfaserplatten" | WI-PR | 0 | A | 7.5 | 1163HWa0812836365 | NEW |  | no |  | 0 | no | 0 | no | Codetext | AllplanAttributes - Ortscode_Geschoßbezeichnung: E02; Positionsnummer_Text: U100
 | H2 Ebene +2 | WI-PR | 1213Wa 0813694846 | yes | Codetext | m² | Trockenbauarbeiten | Wand | "BS-Beplankung; 2-fach Gipsfaserplatten" | WI-PR | 0 | A | 7.5 | 1163HWa0812836365 | NEW |  | no |  | 0 | no | 0 | no | Codetext | AllplanAttributes - Ortscode_Geschoßbezeichnung: E02; Positionsnummer_Text: U100
 | H2 Ebene +2 | WI-PR | 1213Wa 0813695116 | yes | Codetext | m² | Trockenbauarbeiten | Wand | "BS-Beplankung; 2-fach Gipsfaserplatten" | WI-PR | 0 | A | 7.5 | 1163HWa0812836365 | NEW |  | no |  | 0 | no | 0 | no | Codetext | AllplanAttributes - Ortscode_Geschoßbezeichnung: E02; Positionsnummer_Text: U100
 | H2 Ebene +2 | WI-PR | 1213Wa 0813695113 | yes | Codetext | m² | Trockenbauarbeiten | Wand | "BS-Beplankung; 2-fach Gipsfaserplatten" | WI-PR | 0 | A | 7.5 | 1163HWa0812836365 | NEW |  | no |  | 0 | no | 0 | no | Codetext | AllplanAttributes - Ortscode_Geschoßbezeichnung: E02; Positionsnummer_Text: U100
 | H2 Ebene +2 | WI-PR | 1213Wa 0813695114 | yes | Codetext | m² | Trockenbauarbeiten | Wand | "BS-Beplankung; 2-fach Gipsfaserplatten" | WI-PR | 0 | A | 7.5 | 1163HWa0812836365 | NEW |  | no |  | 0 | no | 0 | no | Codetext | AllplanAttributes - Ortscode_Geschoßbezeichnung: E02; Positionsnummer_Text: U100
 | H2 Ebene +2 | WI-PR | 1213Wa 0813695115 | yes | Codetext | m² | Trockenbauarbeiten | Wand | "BS-Beplankung; 2-fach Gipsfaserplatten" | WI-PR | 0 | A | 7.5 | 1163HWa0812836365 | NEW |  | no |  | 0 | no | 0 | no | Codetext | AllplanAttributes - Ortscode_Geschoßbezeichnung: E02; Positionsnummer_Text: U100
 | H2 Ebene +2 | WI-PR | 1213Wa 0813695133 | yes | Codetext | m² | Trockenbauarbeiten | Wand | "BS-Beplankung; 2-fach Gipsfaserplatten" | WI-PR | 0 | A | 7.5 | 1163HWa0812836365 | NEW |  | no |  | 0 | no | 0 | no | Codetext | AllplanAttributes - Ortscode_Geschoßbezeichnung: E02; Positionsnummer_Text: U100
 | H2 Ebene +2 | WI-PR | 1213Wa 0813695136 | yes | Codetext | m² | Trockenbauarbeiten | Wand | "BS-Beplankung; 2-fach Gipsfaserplatten" | WI-PR | 0 | A | 7.5 | 1163HWa0812836365 | NEW |  | no |  | 0 | no | 0 | no | Codetext | AllplanAttributes - Ortscode_Geschoßbezeichnung: E02; Positionsnummer_Text: U100
 | H2 Ebene +2 | WI-PR | 1213Wa 0813695135 | yes | Codetext | m² | Trockenbauarbeiten | Wand | "BS-Beplankung; 2-fach Gipsfaserplatten" | WI-PR | 0 | A | 7.5 | 1163HWa0812836365 | NEW |  | no |  | 0 | no | 0 | no | Codetext | AllplanAttributes - Ortscode_Geschoßbezeichnung: E02; Positionsnummer_Text: U100
 | H2 Ebene +2 | WI-PR | 1213Wa 0813695134 | yes | Codetext | m² | Trockenbauarbeiten | Wand | "BS-Beplankung; 2-fach Gipsfaserplatten" | WI-PR | 0 | A | 7.5 | 1163HWa0812836365 | NEW |  | no |  | 0 | no | 0 | no | Codetext | AllplanAttributes - Ortscode_Geschoßbezeichnung: E02; Positionsnummer_Text: U100
 | H2 Ebene +2 | WI-LB | 1213Wa 0812969918 | yes | Codetext | m² | Trockenbauarbeiten | Wand | Innenwand 1-Schalig | WI-LB | 0 | A | 7.5 | 1213HWa0812968500 | NEW | no | no | REI 60-A1 - D,s2-d0 /A1 | 0 | no |  | no | Codetext | AllplanAttributes - Ortscode_Geschoßbezeichnung: E02; ash_W_Trockenbau_Qualitäten: 6
 | H2 Ebene +2 | WI-STB | 1213Wa 0812969920 | yes | Codetext | m² | Zimmer- und Holzbauarbeiten | Wand | Außenwand 1-Schalig | WI-STB | 0 | A | 7.5 | 1213HWa0812968495 | NEW | yes | no | REI 60-A1 - D,s2-d0 /A1 | 0 | no | 52 | no | Codetext | AllplanAttributes - Ortscode_Geschoßbezeichnung: E02
 | H2 Ebene +2 | WI-LB | 1213Wa 0812985912 | yes | Codetext | m² | Trockenbauarbeiten | Wand | Innenwand 1-Schalig | WI-LB | 0 | A | 7.5 | 1213HWa0812968500 | NEW | no | no | REI 60-A1 - D,s2-d0 /A1 | 0 | no | 0 | no | Codetext | AllplanAttributes - Ortscode_Geschoßbezeichnung: E02; ash_W_Trockenbau_Qualitäten: 6
 | H2 Ebene +2 | WI-HW | 1213Wa 0813695250 | yes | Codetext | m² | Zimmer- und Holzbauarbeiten | Wand | Innenwand 1-Schalig | WI-HW | 0 | A | 7.5 | 1213HWa0812968371 | NEW | yes | no | 0 | 0 | no | 52 | no | Codetext | AllplanAttributes - Ortscode_Geschoßbezeichnung: E02; ash W_laufende Nr. Statik: 3 (W 3.0)
 | H2 Ebene +2 | WI-LB | 1213Wa 0813695456 | yes | Codetext | m² | Trockenbauarbeiten | Wand | Innenwand 1-Schalig | WI-LB | 0 | A | 7.5 | 1213HWa0812968095 | NEW |  | no | 0 | 0 | no |  | no | Codetext | AllplanAttributes - Ortscode_Geschoßbezeichnung: E02; W_Deckenanschluss: Gleitender Deckenanschluss Fall 01; ash_W_Trockenbau_Qualitäten: 6
 | H2 Ebene +2 | WI-LB | 1213Wa 0813695466 | yes | Codetext | m² | Trockenbauarbeiten | Wand | Innenwand 1-Schalig | WI-LB | 0 | A | 7.5 | 1213HWa0812968095 | NEW |  | no | 0 | 0 | no |  | no | Codetext | AllplanAttributes - Ortscode_Geschoßbezeichnung: E02; W_Deckenanschluss: Gleitender Deckenanschluss Fall 01; ash_W_Trockenbau_Qualitäten: 6
 | H2 Ebene +2 | WI-LB | 1213Wa 0813695478 | yes | Codetext | m² | Trockenbauarbeiten | Wand | Innenwand 1-Schalig | WI-LB | 0 | A | 7.5 | 1213HWa0812968095 | NEW |  | no | 0 | 0 | no |  | no | Codetext | AllplanAttributes - Ortscode_Geschoßbezeichnung: E02; W_Deckenanschluss: Gleitender Deckenanschluss Fall 01; ash_W_Trockenbau_Qualitäten: 6
 | H2 Ebene +2 | WI-PR | 1213Wa 0813695505 | yes | Codetext | m² | Trockenbauarbeiten | Wand | "BS-Beplankung; 2-fach Gipsfaserplatten" | WI-PR | 0 | A | 7.5 | 1163HWa0812836365 | NEW |  | no |  | 0 | no | 0 | no | Codetext | AllplanAttributes - Ortscode_Geschoßbezeichnung: E02; Positionsnummer_Text: U100
 | H2 Ebene +2 | WI-PR | 1213Wa 0813695502 | yes | Codetext | m² | Trockenbauarbeiten | Wand | "BS-Beplankung; 2-fach Gipsfaserplatten" | WI-PR | 0 | A | 7.5 | 1163HWa0812836365 | NEW |  | no |  | 0 | no | 0 | no | Codetext | AllplanAttributes - Ortscode_Geschoßbezeichnung: E02; Positionsnummer_Text: U100
 | H2 Ebene +2 | WI-PR | 1213Wa 0813695503 | yes | Codetext | m² | Trockenbauarbeiten | Wand | "BS-Beplankung; 2-fach Gipsfaserplatten" | WI-PR | 0 | A | 7.5 | 1163HWa0812836365 | NEW |  | no |  | 0 | no | 0 | no | Codetext | AllplanAttributes - Ortscode_Geschoßbezeichnung: E02; Positionsnummer_Text: U100
 | H2 Ebene +2 | WI-PR | 1213Wa 0813695504 | yes | Codetext | m² | Trockenbauarbeiten | Wand | "BS-Beplankung; 2-fach Gipsfaserplatten" | WI-PR | 0 | A | 7.5 | 1163HWa0812836365 | NEW |  | no |  | 0 | no | 0 | no | Codetext | AllplanAttributes - Ortscode_Geschoßbezeichnung: E02; Positionsnummer_Text: U100
 | H2 Ebene +2 | WI-LB | 1213Wa 0813697617 | yes | Codetext | m² | Trockenbauarbeiten | Wand | Innenwand 1-Schalig | WI-LB | 0 | A | 7.5 | 1213HWa0812968287 | NEW | no | no | REI 60-A1 - D,s2-d0 /A1 | 0 | no | 47 | no | Codetext | AllplanAttributes - Ortscode_Geschoßbezeichnung: E02; W_Deckenanschluss: Gleitender Deckenanschluss Fall 01; ash_W_Trockenbau_Qualitäten: 4
im Zusammenhang mit der Möblierung anzufertigen | H2 Ebene +2 | WI-RIR | 1213Wa 0813695060 | yes | Codetext | m² | Tischlerarbeiten | Wand | im Zusammenhang mit der Möblierung anzufertigen | WI-RIR | 0 | A | 7.5 |  | NEW | no | no | 0 | 0 | no | 47 | no | Codetext | AllplanAttributes - Ortscode_Geschoßbezeichnung: E02; W_Deckenanschluss: Gleitender Deckenanschluss Fall 01; ash_W_Trockenbau_Qualitäten: 1b
im Zusammenhang mit der Möblierung anzufertigen | H2 Ebene +2 | WI-RIR | 1213Wa 0813455715 | yes | Codetext | m² | Tischlerarbeiten | Wand | im Zusammenhang mit der Möblierung anzufertigen | WI-RIR | 0 | A | 7.5 |  | NEW | no | no | 0 | 0 | no | 47 | no | Codetext | AllplanAttributes - Ortscode_Geschoßbezeichnung: E02; W_Deckenanschluss: Gleitender Deckenanschluss Fall 01; ash_W_Trockenbau_Qualitäten: 1b
im Zusammenhang mit der Möblierung anzufertigen | H2 Ebene +2 | WI-RIR | 1213Wa 0813446030 | yes | Codetext | m² | Tischlerarbeiten | Wand | im Zusammenhang mit der Möblierung anzufertigen | WI-RIR | 0 | A | 7.5 |  | NEW | no | no | 0 | 0 | no | 47 | no | Codetext | AllplanAttributes - Ortscode_Geschoßbezeichnung: E02; W_Deckenanschluss: Gleitender Deckenanschluss Fall 01; ash_W_Trockenbau_Qualitäten: 1b
 | H2 Ebene +2 | WI-IW | 1213Wa 0813057758 | yes | Codetext | m² | Trockenbauarbeiten | Wand | Installationswand | WI-IW | 0 | A | 7.5 | 1213HWa0812968250 | NEW | no | no | 0 | 0 | no | 47 | no | Codetext | AllplanAttributes - Ortscode_Geschoßbezeichnung: E02; W_Deckenanschluss: Gleitender Deckenanschluss Fall 03; ash_W_Trockenbau_Qualitäten: 14
 | H2 Ebene +2 | Installationsraum | 1213Wa 0813701056 | yes | Codetext | m² | Trockenbauarbeiten | Wand | Installationswand | Installationsraum | 0 | A | 7.5 | 1213HWa0812968250 | NEW | no | no | 0 | 0 | no | 0 | no | Codetext | AllplanAttributes - Ortscode_Geschoßbezeichnung: E02
 | H2 Ebene +2 | WI-IW | 1213Wa 0813701057 | yes | Codetext | m² | Trockenbauarbeiten | Wand | Installationswand | WI-IW | 0 | A | 7.5 | 1213HWa0812968250 | NEW | no | no | 0 | 0 | no | 47 | no | Codetext | AllplanAttributes - Ortscode_Geschoßbezeichnung: E02; W_Deckenanschluss: Gleitender Deckenanschluss Fall 03; ash_W_Trockenbau_Qualitäten: 14
 | H2 Ebene +2 | WI-LB | 1213Wa 0813701208 | yes | Codetext | m² | Trockenbauarbeiten | Wand | Innenwand 1-Schalig | WI-LB | 0 | A | 7.5 | 1213HWa0812971325 | NEW | no | no | 0 | 0 | no | 47 | no | Codetext | AllplanAttributes - Ortscode_Geschoßbezeichnung: E02; W_Deckenanschluss: Gleitender Deckenanschluss Fall 03; ash_W_Trockenbau_Qualitäten: 1b
 | H2 Ebene +2 | WI-LB | 1213Wa 0813701232 | yes | Codetext | m² | Trockenbauarbeiten | Wand | Innenwand 1-Schalig | WI-LB | 0 | A | 7.5 | 1213HWa0812971325 | NEW | no | no | 0 | 0 | no | 47 | no | Codetext | AllplanAttributes - Ortscode_Geschoßbezeichnung: E02; W_Deckenanschluss: Gleitender Deckenanschluss Fall 03; ash_W_Trockenbau_Qualitäten: 1b
 | H2 Ebene +2 | WI-LW 60 | 1213Wa 0812986025 | yes |  | m² | Trockenbauarbeiten | Wand | Innenwand 1-Schalig | WI-LW 60 |  |  | 7.5 | 1213HWa0812968106 | NEW | no | no | 0 | AllplanAttributes - Ortscode_Geschoßbezeichnung: E02; ash_W_Trockenbau_Qualitäten: 12a
 | H2 Ebene +2 | WI-GKF | 1213Wa 0813701506 | yes | Codetext | m² | Trockenbauarbeiten | Wand | "BS-Beplankung; 2-fach Gipsfaserplatten" | WI-GKF | 0 | A | 7.5 | 1213HWa0812969739 | NEW | no | no | EI 60-A1 - D,s2,d0 +A1 | 0 | no | 0 | no | Codetext | AllplanAttributes - Ortscode_Geschoßbezeichnung: E02
 | H2 Ebene +2 | WI-GKF | 1213Wa 0813701513 | yes | Codetext | m² | Trockenbauarbeiten | Wand | "BS-Beplankung; 2-fach Gipsfaserplatten" | WI-GKF | 0 | A | 7.5 | 1213HWa0812969739 | NEW | no | no | EI 60-A1 - D,s2,d0 +A1 | 0 | no | 0 | no | Codetext | AllplanAttributes - Ortscode_Geschoßbezeichnung: E02
 | H2 Ebene +2 | WI-GKF | 1213Wa 0813701525 | yes | Codetext | m² | Trockenbauarbeiten | Wand | "BS-Beplankung; 2-fach Gipsfaserplatten" | WI-GKF | 0 | A | 7.5 | 1213HWa0812969739 | NEW | no | no | EI 60-A1 - D,s2,d0 +A1 | 0 | no | 0 | no | Codetext | AllplanAttributes - Ortscode_Geschoßbezeichnung: E02
 | H2 Ebene +2 | WI-GKF | 1213Wa 0813701539 | yes | Codetext | m² | Trockenbauarbeiten | Wand | "BS-Beplankung; 2-fach Gipsfaserplatten" | WI-GKF | 0 | A | 7.5 | 1213HWa0812969739 | NEW | no | no | EI 60-A1 - D,s2,d0 +A1 | 0 | no | 0 | no | Codetext | AllplanAttributes - Ortscode_Geschoßbezeichnung: E02
 | H2 Ebene +2 | WI-GKF | 1213Wa 0813701558 | yes | Codetext | m² | Trockenbauarbeiten | Wand | "BS-Beplankung; 2-fach Gipsfaserplatten" | WI-GKF | 0 | A | 7.5 | 1213HWa0812969739 | NEW | no | no | EI 60-A1 - D,s2,d0 +A1 | 0 | no | 0 | no | Codetext | AllplanAttributes - Ortscode_Geschoßbezeichnung: E02
 | H2 Ebene +2 | WI-GKF | 1213Wa 0813701565 | yes | Codetext | m² | Trockenbauarbeiten | Wand | "BS-Beplankung; 2-fach Gipsfaserplatten" | WI-GKF | 0 | A | 7.5 | 1213HWa0812969739 | NEW | no | no | EI 60-A1 - D,s2,d0 +A1 | 0 | no | 0 | no | Codetext | AllplanAttributes - Ortscode_Geschoßbezeichnung: E02
 | H2 Ebene +2 | WI-GKF | 1213Wa 0813701577 | yes | Codetext | m² | Trockenbauarbeiten | Wand | "BS-Beplankung; 2-fach Gipsfaserplatten" | WI-GKF | 0 | A | 7.5 | 1213HWa0812969739 | NEW | no | no | EI 60-A1 - D,s2,d0 +A1 | 0 | no | 0 | no | Codetext | AllplanAttributes - Ortscode_Geschoßbezeichnung: E02
 | H2 Ebene +2 | WI-GKF | 1213Wa 0813701591 | yes | Codetext | m² | Trockenbauarbeiten | Wand | "BS-Beplankung; 2-fach Gipsfaserplatten" | WI-GKF | 0 | A | 7.5 | 1213HWa0812969739 | NEW | no | no | EI 60-A1 - D,s2,d0 +A1 | 0 | no | 0 | no | Codetext | AllplanAttributes - Ortscode_Geschoßbezeichnung: E02
 | H2 Ebene +2 | WI-LW 60 | 1213Wa 0812986078 | yes |  | m² | Trockenbauarbeiten | Wand | Innenwand 1-Schalig | WI-LW 60 |  |  | 7.5 | 1213HWa0812968106 | NEW | no | no | 0 | AllplanAttributes - Ortscode_Geschoßbezeichnung: E02; ash_W_Trockenbau_Qualitäten: 12a
 | H2 Ebene +2 | WI-HW 60 | 1213Wa 0813703109 | yes |  | m² | Zimmer- und Holzbauarbeiten | Wand | Innenwand 1-Schalig | WI-HW 60 |  |  | 7.5 | 1163HWa0812430471 | NEW | no | no | REI-M 60-D,s2,d0 + A1 | AllplanAttributes - Ortscode_Geschoßbezeichnung: E02; ash W_laufende Nr. Statik: 7 (W 6.0-1); Positionsnummer_Text: U100
 | H2 Ebene +2 | WI-GKF | 1213Wa 0813703110 | yes | Codetext | m² | Trockenbauarbeiten | Wand | Innenwand 1-Schalig | WI-GKF | 0 | A | 7.5 | 1213HWa0812969739 | NEW | no | no | EI 60-A1 - D,s2,d0 +A1 | 0 | no | 0 | no | Codetext | AllplanAttributes - Ortscode_Geschoßbezeichnung: E02
 | H2 Ebene +2 | WI-HW 60 | 1213Wa 0813703117 | yes |  | m² | Zimmer- und Holzbauarbeiten | Wand | Innenwand 1-Schalig | WI-HW 60 |  |  | 7.5 | 1163HWa0812430471 | NEW | no | no | REI-M 60-D,s2,d0 + A1 | AllplanAttributes - Ortscode_Geschoßbezeichnung: E02; ash W_laufende Nr. Statik: 7 (W 6.0-1); Positionsnummer_Text: U100
 | H2 Ebene +2 | WI-GKF | 1213Wa 0813703118 | yes | Codetext | m² | Trockenbauarbeiten | Wand | Innenwand 1-Schalig | WI-GKF | 0 | A | 7.5 | 1213HWa0812969739 | NEW | no | no | EI 60-A1 - D,s2,d0 +A1 | 0 | no | 0 | no | Codetext | AllplanAttributes - Ortscode_Geschoßbezeichnung: E02
 | H2 Ebene +2 | WI-HW 60 | 1213Wa 0813703135 | yes |  | m² | Zimmer- und Holzbauarbeiten | Wand | Innenwand 1-Schalig | WI-HW 60 |  |  | 7.5 | 1163HWa0812430471 | NEW | no | no | REI-M 60-D,s2,d0 + A1 | AllplanAttributes - Ortscode_Geschoßbezeichnung: E02; ash W_laufende Nr. Statik: 7 (W 6.0-1); Positionsnummer_Text: U100
 | H2 Ebene +2 | WI-GKF | 1213Wa 0813703136 | yes | Codetext | m² | Trockenbauarbeiten | Wand | Innenwand 1-Schalig | WI-GKF | 0 | A | 7.5 | 1213HWa0812969739 | NEW | no | no | EI 60-A1 - D,s2,d0 +A1 | 0 | no | 0 | no | Codetext | AllplanAttributes - Ortscode_Geschoßbezeichnung: E02
 | H2 Ebene +2 | WI-HW 60 | 1213Wa 0813703156 | yes |  | m² | Zimmer- und Holzbauarbeiten | Wand | Innenwand 1-Schalig | WI-HW 60 |  |  | 7.5 | 1163HWa0812430471 | NEW | no | no | REI-M 60-D,s2,d0 + A1 | AllplanAttributes - Ortscode_Geschoßbezeichnung: E02; ash W_laufende Nr. Statik: 7 (W 6.0-1); Positionsnummer_Text: U100
 | H2 Ebene +2 | WI-HW 60 | 1213Wa 0813703275 | yes |  | m² | Zimmer- und Holzbauarbeiten | Wand | Innenwand 1-Schalig | WI-HW 60 |  |  | 7.5 | 1163HWa0812430471 | NEW | no | no | REI-M 60-D,s2,d0 + A1 | AllplanAttributes - Ortscode_Geschoßbezeichnung: E02; ash W_laufende Nr. Statik: 7 (W 6.0-1); Positionsnummer_Text: U100
 | H2 Ebene +2 | WI-GKF | 1213Wa 0813703276 | yes | Codetext | m² | Trockenbauarbeiten | Wand | Innenwand 1-Schalig | WI-GKF | 0 | A | 7.5 | 1213HWa0812969739 | NEW | no | no | EI 60-A1 - D,s2,d0 +A1 | 0 | no | 0 | no | Codetext | AllplanAttributes - Ortscode_Geschoßbezeichnung: E02
 | H2 Ebene +2 | WI-HW 60 | 1213Wa 0813703285 | yes |  | m² | Zimmer- und Holzbauarbeiten | Wand | Innenwand 1-Schalig | WI-HW 60 |  |  | 7.5 | 1163HWa0812430471 | NEW | no | no | REI-M 60-D,s2,d0 + A1 | AllplanAttributes - Ortscode_Geschoßbezeichnung: E02; ash W_laufende Nr. Statik: 7 (W 6.0-1); Positionsnummer_Text: U100
 | H2 Ebene +2 | WI-GKF | 1213Wa 0813703286 | yes | Codetext | m² | Trockenbauarbeiten | Wand | Innenwand 1-Schalig | WI-GKF | 0 | A | 7.5 | 1213HWa0812969739 | NEW | no | no | EI 60-A1 - D,s2,d0 +A1 | 0 | no | 0 | no | Codetext | AllplanAttributes - Ortscode_Geschoßbezeichnung: E02
 | H2 Ebene +2 | WI-HW 60 | 1213Wa 0813703304 | yes |  | m² | Zimmer- und Holzbauarbeiten | Wand | Innenwand 1-Schalig | WI-HW 60 |  |  | 7.5 | 1163HWa0812430471 | NEW | no | no | REI-M 60-D,s2,d0 + A1 | AllplanAttributes - Ortscode_Geschoßbezeichnung: E02; ash W_laufende Nr. Statik: 7 (W 6.0-1); Positionsnummer_Text: U100
 | H2 Ebene +2 | WI-GKF | 1213Wa 0813703305 | yes | Codetext | m² | Trockenbauarbeiten | Wand | Innenwand 1-Schalig | WI-GKF | 0 | A | 7.5 | 1213HWa0812969739 | NEW | no | no | EI 60-A1 - D,s2,d0 +A1 | 0 | no | 0 | no | Codetext | AllplanAttributes - Ortscode_Geschoßbezeichnung: E02
 | H2 Ebene +2 | WI-HW 60 | 1213Wa 0813703325 | yes |  | m² | Zimmer- und Holzbauarbeiten | Wand | Innenwand 1-Schalig | WI-HW 60 |  |  | 7.5 | 1163HWa0812430471 | NEW | no | no | REI-M 60-D,s2,d0 + A1 | AllplanAttributes - Ortscode_Geschoßbezeichnung: E02; ash W_laufende Nr. Statik: 7 (W 6.0-1); Positionsnummer_Text: U100
 | H2 Ebene +2 | WI-GKF | 1213Wa 0813703326 | yes | Codetext | m² | Trockenbauarbeiten | Wand | Innenwand 1-Schalig | WI-GKF | 0 | A | 7.5 | 1213HWa0812969739 | NEW | no | no | EI 60-A1 - D,s2,d0 +A1 | 0 | no | 0 | no | Codetext | AllplanAttributes - Ortscode_Geschoßbezeichnung: E02
 | H2 Ebene +2 | WI-LB | 1213Wa 0813054749 | yes | Codetext | m² | Trockenbauarbeiten | Wand | Innenwand 1-Schalig | WI-LB | 0 | A | 7.5 | 1213HWa0813054747 | NEW | no | no | 0 | 0 | no | 0 | no | Codetext | AllplanAttributes - Ortscode_Geschoßbezeichnung: E02; ash_W_Trockenbau_Qualitäten: 8
 | H2 Ebene +2 | WI-LB | 1213Wa 0813640128 | yes | Codetext | m² | Trockenbauarbeiten | Wand | Innenwand 1-Schalig | WI-LB | 0 | A | 7.5 | 1213HWa0813054747 | NEW | no | no | 0 | 0 | no | 0 | no | Codetext | AllplanAttributes - Ortscode_Geschoßbezeichnung: E02; ash_W_Trockenbau_Qualitäten: 6
 | H2 Ebene +2 | WI-HW 60 | 1213Wa 0813410010 | yes | Codetext | m² | Zimmer- und Holzbauarbeiten | Wand | Innenwand 1-Schalig | WI-HW 60 | 0 | A | 7.5 | 1213HWa0812968265 | NEW | no | no | REI 60-A1 - D,s2-d0 +A1 | 0 | no | 0 | no | Codetext | AllplanAttributes - Ortscode_Geschoßbezeichnung: E02; ash_W_Trockenbau_Qualitäten: 6; Sicherheitsklasse: -; ash W_laufende Nr. Statik: 3 (W 3.0)
 | H2 Ebene +2 | WI-HW 60 | 1213Wa 0812970151 | yes | Codetext | m² | Zimmer- und Holzbauarbeiten | Wand | Innenwand 1-Schalig | WI-HW 60 | 0 | A | 7.5 | 1213HWa0812968134 | NEW |  | no | 0 | 0 | no | 0 | no | Codetext | AllplanAttributes - Ortscode_Geschoßbezeichnung: E02; Sicherheitsklasse: -; ash W_laufende Nr. Statik: 3 (W 3.0)
 | H2 Ebene +2 | WI-HW 60 | 1213Wa 0812986067 | yes | Codetext | m² | Zimmer- und Holzbauarbeiten | Wand | Innenwand 1-Schalig | WI-HW 60 | 0 | A | 7.5 | 1213HWa0812968177 | NEW | no | no | REI 60-A1 - D,s2-d0 +A1 | 0 | no | 0 | no | Codetext | AllplanAttributes - Ortscode_Geschoßbezeichnung: E02; Sicherheitsklasse: -; ash W_laufende Nr. Statik: 3 (W 3.0)
 | H2 Ebene +2 | WI-HW 60 | 1213Wa 0812970030 | yes | Codetext | m² | Zimmer- und Holzbauarbeiten | Wand | Innenwand 1-Schalig | WI-HW 60 | 0 | A | 7.5 | 1213HWa0812968178 | NEW | no | no | 0 | 0 | no | 0 | no | Codetext | AllplanAttributes - Ortscode_Geschoßbezeichnung: E02; Sicherheitsklasse: -; ash W_laufende Nr. Statik: 3 (W 3.0)
 | H2 Ebene +2 | WI-HW 60 | 1213Wa 0812970434 | yes | Codetext | m² | Zimmer- und Holzbauarbeiten | Wand | Innenwand 1-Schalig | WI-HW 60 | 0 | A | 7.5 | 1213HWa0812968107 | NEW | no | no | REI 60-A1 - D,s2-d0 +A1 | 0 | no | 52 | no | Codetext | AllplanAttributes - Ortscode_Geschoßbezeichnung: E02; Sicherheitsklasse: -; ash W_laufende Nr. Statik: 3 (W 3.0)
 | H2 Ebene +2 | WI-LB | 1213Wa 0813086010 | yes | Codetext | m² | Trockenbauarbeiten | Wand | Innenwand 1-Schalig | WI-LB | 0 | A | 7.5 | 1213HWa0812968107 | NEW | no | no | REI 60-A1 - D,s2-d0 /A1 | 0 | no | 52 | no | Codetext | AllplanAttributes - Ortscode_Geschoßbezeichnung: E02; ash_W_Trockenbau_Qualitäten: 6; Sicherheitsklasse: -
 | H2 Ebene +2 | WI-LB | 1213Wa 0812970156 | yes | Codetext | m² | Trockenbauarbeiten | Wand | Innenwand 1-Schalig | WI-LB | 0 | A | 7.5 | 1213HWa0812968261 | NEW | no | no | 0 | 0 | no | 0 | no | Codetext | AllplanAttributes - Ortscode_Geschoßbezeichnung: E02; W_Deckenanschluss: Gleitender Deckenanschluss Fall 03; ash_W_Trockenbau_Qualitäten: 1b
 | H2 Ebene +2 | WI-IW | 1213Wa 0812970305 | yes | Codetext | m² | Trockenbauarbeiten | Wand | Installationswand | WI-IW | 0 | A | 7.5 | 1213HWa0812968248 | NEW | no | no | 0 | 0 | no | 0 | no | Codetext | AllplanAttributes - Ortscode_Geschoßbezeichnung: E02; W_Deckenanschluss: Gleitender Deckenanschluss Fall 03; ash_W_Trockenbau_Qualitäten: 2
 | H2 Ebene +2 | Installationsraum | 1213Wa 0812970307 | yes | Codetext | m² | Trockenbauarbeiten | Wand | Installationswand | Installationsraum | 0 | A | 7.5 | 1213HWa0812968248 | NEW | no | no | 0 | 0 | no | 0 | no | Codetext | AllplanAttributes - Ortscode_Geschoßbezeichnung: E02
 | H2 Ebene +2 | WI-LB | 1213Wa 0812970422 | yes | Codetext | m² | Trockenbauarbeiten | Wand | Innenwand 1-Schalig | WI-LB | 0 | A | 7.5 | 1213HWa0812968239 | NEW | no | no | 0 | 0 | no | 0 | no | Codetext | AllplanAttributes - Ortscode_Geschoßbezeichnung: E02; W_Deckenanschluss: Gleitender Deckenanschluss Fall 03; ash_W_Trockenbau_Qualitäten: 10a
 | H2 Ebene +2 | WI-IW | 1213Wa 0812970830 | yes | Codetext | m² | Trockenbauarbeiten | Wand | Installationswand | WI-IW | 0 | A | 7.5 | 1213HWa0812968250 | NEW | no | no | 0 | 0 | no | 47 | no | Codetext | AllplanAttributes - Ortscode_Geschoßbezeichnung: E02; W_Deckenanschluss: Gleitender Deckenanschluss Fall 03; ash_W_Trockenbau_Qualitäten: 11
 | H2 Ebene +2 | Installationsraum | 1213Wa 0812970832 | yes | Codetext | m² | Trockenbauarbeiten | Wand | Installationswand | Installationsraum | 0 | A | 7.5 | 1213HWa0812968250 | NEW | no | no | 0 | 0 | no | 0 | no | Codetext | AllplanAttributes - Ortscode_Geschoßbezeichnung: E02
 | H2 Ebene +2 | WI-IW | 1213Wa 0812970828 | yes | Codetext | m² | Trockenbauarbeiten | Wand | Installationswand | WI-IW | 0 | A | 7.5 | 1213HWa0812968250 | NEW | no | no | 0 | 0 | no | 47 | no | Codetext | AllplanAttributes - Ortscode_Geschoßbezeichnung: E02; W_Deckenanschluss: Gleitender Deckenanschluss Fall 03; ash_W_Trockenbau_Qualitäten: 11
 | H2 Ebene +2 | WI-LB | 1213Wa 0812970975 | yes | Codetext | m² | Trockenbauarbeiten | Wand | Innenwand 1-Schalig | WI-LB | 0 | A | 7.5 | 1213HWa0812968557 | NEW | no | no | 0 | 0 | no | 47 | no | Codetext | AllplanAttributes - Ortscode_Geschoßbezeichnung: E02; W_Deckenanschluss: Gleitender Deckenanschluss Fall 03; ash_W_Trockenbau_Qualitäten: 1c
 | H2 Ebene +2 | WI-VS | 1213Wa 0813062183 | yes | Codetext | m² | Trockenbauarbeiten | Wand | Installationswand | WI-VS | 0 | A | 7.5 | 1213HWa0813062182 | NEW | no | no | 0 | 0 | no | 0 | no | Codetext | AllplanAttributes - Ortscode_Geschoßbezeichnung: E02; ash_W_Trockenbau_Qualitäten: 16
 | H2 Ebene +2 | WI-LB | 1213Wa 0813021726 | yes | Codetext | m² | Trockenbauarbeiten | Wand | Innenwand 1-Schalig | WI-LB | 0 | A | 7.5 | 1213HWa0813021725 | NEW |  | no | 0 | 0 | no | 0 | no | Codetext | AllplanAttributes - Ortscode_Geschoßbezeichnung: E02; W_Deckenanschluss: Gleitender Deckenanschluss Fall 01; ash_W_Trockenbau_Qualitäten: 13
 | H2 Ebene +2 | WI-LB | 1213Wa 0813569053 | yes | Codetext | m² | Trockenbauarbeiten | Wand | Innenwand 1-Schalig | WI-LB | 0 | A | 7.5 | 1213HWa0812968099 | NEW |  | no | REI 60-A1 - D,s2-d0 +A1 | 0 | no | 0 | no | Codetext | AllplanAttributes - Ortscode_Geschoßbezeichnung: E02; W_Deckenanschluss: Gleitender Deckenanschluss Fall 01; ash_W_Trockenbau_Qualitäten: 1a
 | H2 Ebene +2 | WI-IW | 1213Wa 0812970932 | yes | Codetext | m² | Trockenbauarbeiten | Wand | Installationswand | WI-IW | 0 | A | 7.5 | 1213HWa0812968200 | NEW |  | no | 0 | 0 | no | 47 | no | Codetext | AllplanAttributes - Ortscode_Geschoßbezeichnung: E02; W_Deckenanschluss: Gleitender Deckenanschluss Fall 01; ash_W_Trockenbau_Qualitäten: 19
 | H2 Ebene +2 | Installationsraum | 1213Wa 0812970937 | yes | Codetext | m² | Trockenbauarbeiten | Wand | Installationswand | Installationsraum | 0 | A | 7.5 | 1213HWa0812968200 | NEW |  | no | 0 | 0 | no | 0 | no | Codetext | AllplanAttributes - Ortscode_Geschoßbezeichnung: E02
 | H2 Ebene +2 | WI-IW | 1213Wa 0813643783 | yes | Codetext | m² | Trockenbauarbeiten | Wand | Installationswand | WI-IW | 0 | A | 7.5 | 1213HWa0812968200 | NEW |  | no | 0 | 0 | no | 47 | no | Codetext | AllplanAttributes - Ortscode_Geschoßbezeichnung: E02; W_Deckenanschluss: Gleitender Deckenanschluss Fall 01; ash_W_Trockenbau_Qualitäten: 19
 | H2 Ebene +2 | WI-LW 60 | 1213Wa 0812986054 | yes | Codetext | m² | Trockenbauarbeiten | Wand | Innenwand 1-Schalig | WI-LW 60 | 0 | A | 7.5 | 1213HWa0812968137 | NEW | no | no | REI 60-A1 - D,s2-d0 +A1 | 0 | no | 0 | no | Codetext | AllplanAttributes - Ortscode_Geschoßbezeichnung: E02; W_Deckenanschluss: Gleitender Deckenanschluss Fall 01; ash_W_Trockenbau_Qualitäten: 12b; Sicherheitsklasse: -
 | H2 Ebene +2 | WI-LW 60 | 1213Wa 0812986461 | yes |  | m² | Trockenbauarbeiten | Wand | Innenwand 1-Schalig | WI-LW 60 |  |  | 7.5 | 1213HWa0812969861 | NEW | no | no | REI-M 60-D,s2,d0 + A1 | AllplanAttributes - Ortscode_Geschoßbezeichnung: E02; ash_W_Trockenbau_Qualitäten: 12a
 | H2 Ebene +2 | WI-LB | 1213Wa 0813668292 | yes | Codetext | m² | Trockenbauarbeiten | Wand | Innenwand 1-Schalig | WI-LB | 0 | A | 7.5 | 1213HWa0813055490 | NEW | no | no | 0 | 0 | no | 0 | no | Codetext | AllplanAttributes - Ortscode_Geschoßbezeichnung: E02; ash_W_Trockenbau_Qualitäten: 18
 | H2 Ebene +2 | WI-IW | 1213Wa 0813056954 | yes | Codetext | m² | Trockenbauarbeiten | Wand | Installationswand | WI-IW | 0 | A | 7.5 | 1213HWa0812968250 | NEW | no | no | 0 | 0 | no | 47 | no | Codetext | AllplanAttributes - Ortscode_Geschoßbezeichnung: E02; W_Deckenanschluss: Gleitender Deckenanschluss Fall 03; ash_W_Trockenbau_Qualitäten: 14
 | H2 Ebene +2 | Installationsraum | 1213Wa 0813701037 | yes | Codetext | m² | Trockenbauarbeiten | Wand | Installationswand | Installationsraum | 0 | A | 7.5 | 1213HWa0812968250 | NEW | no | no | 0 | 0 | no | 0 | no | Codetext | AllplanAttributes - Ortscode_Geschoßbezeichnung: E02
 | H2 Ebene +2 | WI-IW | 1213Wa 0813701038 | yes | Codetext | m² | Trockenbauarbeiten | Wand | Installationswand | WI-IW | 0 | A | 7.5 | 1213HWa0812968250 | NEW | no | no | 0 | 0 | no | 47 | no | Codetext | AllplanAttributes - Ortscode_Geschoßbezeichnung: E02; W_Deckenanschluss: Gleitender Deckenanschluss Fall 03; ash_W_Trockenbau_Qualitäten: 14
 | H2 Ebene +2 | WI-STB | 1213Wa 0812985989 | yes | Codetext | m² | Zimmer- und Holzbauarbeiten | Wand | Außenwand 1-Schalig | WI-STB | 0 | A | 7.5 | 1213HWa0812968515 | NEW | yes | no | REI 60-A1 - D,s2-d0 /A1 | 0 | no | 0 | no | Codetext | AllplanAttributes - Ortscode_Geschoßbezeichnung: E02
 | H2 Ebene +2 | WI-LB | 1213Wa 0813705741 | yes | Codetext | m² | Trockenbauarbeiten | Wand | Außenwand 1-Schalig | WI-LB | 0 | A | 7.5 | 1213HWa0812968515 | NEW | no | no | REI 60-A1 - D,s2-d0 /A1 | 0 | no | 0 | no | Codetext | AllplanAttributes - Ortscode_Geschoßbezeichnung: E02; ash_W_Trockenbau_Qualitäten: 9
 | H2 Ebene +2 | WI-STB | 1213Wa 0812971285 | yes | Codetext | m² | Zimmer- und Holzbauarbeiten | Wand | Außenwand 1-Schalig | WI-STB | 0 | A | 7.5 | 1213HWa0812968515 | NEW | yes | no | REI 60-A1 - D,s2-d0 /A1 | 0 | no | 0 | no | Codetext | AllplanAttributes - Ortscode_Geschoßbezeichnung: E02
 | H2 Ebene +2 | WI-LB | 1213Wa 0813705721 | yes | Codetext | m² | Trockenbauarbeiten | Wand | Außenwand 1-Schalig | WI-LB | 0 | A | 7.5 | 1213HWa0812968515 | NEW | no | no | REI 60-A1 - D,s2-d0 /A1 | 0 | no | 0 | no | Codetext | AllplanAttributes - Ortscode_Geschoßbezeichnung: E02; ash_W_Trockenbau_Qualitäten: 9
 | H2 Ebene +2 | Installationsraum | 1213Wa 0813665649 | yes | Codetext | m² | Trockenbauarbeiten | Wand | Innenwand 1-Schalig | Installationsraum | 0 | A | 7.5 | 1213HWa0812968157 | NEW | no | no | 0 | 0 | no | 0 | no | Codetext | AllplanAttributes - Ortscode_Geschoßbezeichnung: E02
 | H2 Ebene +2 | WI-LB | 1213Wa 0813665650 | yes | Codetext | m² | Trockenbauarbeiten | Wand | Innenwand 1-Schalig | WI-LB | 0 | A | 7.5 | 1213HWa0812968457 | NEW | no | no | REI 60-A1 - D,s2-d0 /A1 | 0 | no |  | no | Codetext | AllplanAttributes - Ortscode_Geschoßbezeichnung: E02; ash_W_Trockenbau_Qualitäten: 16
 | H2 Ebene +2 | WI-LB | 1213Wa 0813192447 | yes | Codetext | m² | Trockenbauarbeiten | Wand | Innenwand 1-Schalig | WI-LB | 0 | A | 7.5 | 1213HWa0813192446 | NEW | no | no | REI 60-A1 - D,s2-d0 /A1 | 0 | no | 0 | no | Codetext | AllplanAttributes - Ortscode_Geschoßbezeichnung: E02; ash_W_Trockenbau_Qualitäten: 9
 | H2 Ebene +2 | WI-LB | 1213Wa 0813496905 | yes | Codetext | m² | Trockenbauarbeiten | Wand | Innenwand 1-Schalig | WI-LB | 0 | A | 7.5 | 1213HWa0813192446 | NEW | no | no | REI 60-A1 - D,s2-d0 /A1 | 0 | no | 0 | no | Codetext | AllplanAttributes - Ortscode_Geschoßbezeichnung: E02; ash_W_Trockenbau_Qualitäten: 9
 | H2 Ebene +2 | WI-LB | 1213Wa 0812986063 | yes | Codetext | m² | Trockenbauarbeiten | Wand | Innenwand 1-Schalig | WI-LB | 0 | A | 7.5 | 1213HWa0812968265 | NEW | no | no | REI 60-A1 - D,s2-d0 /A1 | 0 | no | 52 | no | Codetext | AllplanAttributes - Ortscode_Geschoßbezeichnung: E02; ash_W_Trockenbau_Qualitäten: 6; Sicherheitsklasse: -
 | H2 Ebene +2 | WI-HW 60 | 1213Wa 0813088628 | yes | Codetext | m² | Zimmer- und Holzbauarbeiten | Wand | Innenwand 1-Schalig | WI-HW 60 | 0 | A | 7.5 | 1213HWa0812968265 | NEW | no | no | REI 60-A1 - D,s2-d0 +A1 | 0 | no | 52 | no | Codetext | AllplanAttributes - Ortscode_Geschoßbezeichnung: E02; Sicherheitsklasse: -; ash W_laufende Nr. Statik: 3 (W 3.0)
 | H2 Ebene +2 | WI-IW | 1213Wa 0813061856 | yes | Codetext | m² | Trockenbauarbeiten | Wand | Installationswand | WI-IW | 0 | A | 7.5 | 1213HWa0813061855 | NEW | no | no | 0 | 0 | no | 0 | no | Codetext | AllplanAttributes - Ortscode_Geschoßbezeichnung: E02; ash_W_Trockenbau_Qualitäten: 16
 | H2 Ebene +2 | WI-LB | 1213Wa 0812986166 | yes | Codetext | m² | Trockenbauarbeiten | Wand | Innenwand 1-Schalig | WI-LB | 0 | A | 7.5 | 1213HWa0812968043 | NEW | no | no | 0 | 0 | no |  | no | Codetext | AllplanAttributes - Ortscode_Geschoßbezeichnung: E02; W_Deckenanschluss: Gleitender Deckenanschluss Fall 01; ash_W_Trockenbau_Qualitäten: 4
 | H2 Ebene +2 | Installationsraum | 1213Wa 0812970482 | yes | Codetext | m² | Trockenbauarbeiten | Wand | Installationswand | Installationsraum | 0 | A | 7.5 | 1213HWa0812968160 | NEW |  | no | 0 | 0 | no | 0 | no | Codetext | AllplanAttributes - Ortscode_Geschoßbezeichnung: E02
 | H2 Ebene +2 | WI-VS | 1213Wa 0812970484 | yes | Codetext | m² | Trockenbauarbeiten | Wand | Installationswand | WI-VS | 0 | A | 7.5 | 1213HWa0812968160 | NEW |  | no | 0 | 0 | no | 0 | no | Codetext | AllplanAttributes - Ortscode_Geschoßbezeichnung: E02; W_Deckenanschluss: Gleitender Deckenanschluss Fall 01; ash_W_Trockenbau_Qualitäten: 5
 | H2 Ebene +2 | WI-LB | 1213Wa 0813198749 | yes | Codetext | m² | Trockenbauarbeiten | Wand | Innenwand 1-Schalig | WI-LB | 0 | A | 7.5 | 1163HWa0814107885 | NEW |  | no | 0 | 0 | no | 47 | no | Codetext | AllplanAttributes - Ortscode_Geschoßbezeichnung: E02; W_Deckenanschluss: Gleitender Deckenanschluss Fall 01; ash_W_Trockenbau_Qualitäten: 1d
im Zusammenhang mit der Möblierung anzufertigen | H2 Ebene +2 | WI-LB | 1213Wa 0813692136 | yes | Codetext | m² | Trockenbauarbeiten | Wand | im Zusammenhang mit der Möblierung anzufertigen | WI-LB | 0 | A | 7.5 |  | NEW | no | no | 0 | 0 | no | 47 | no | Codetext | AllplanAttributes - Ortscode_Geschoßbezeichnung: E02; W_Deckenanschluss: Gleitender Deckenanschluss Fall 01; ash_W_Trockenbau_Qualitäten: 8
 | H2 Ebene +2 | WI-HW 60 | 1213Wa 0812986412 | yes | Codetext | m² | Zimmer- und Holzbauarbeiten | Wand | Innenwand 1-Schalig | WI-HW 60 | 0 | A | 7.5 | 1213HWa0812968424 | NEW | yes | no | 0 | 0 | no | 0 | no | Codetext | AllplanAttributes - Ortscode_Geschoßbezeichnung: E02; ash W_laufende Nr. Statik: 3 (W 3.0)
 | H2 Ebene +2 | WI-LB | 1213Wa 0813206858 | yes | Codetext | m² | Trockenbauarbeiten | Wand | Innenwand 1-Schalig | WI-LB | 0 | A | 7.5 | 1113HWa0812553533 | NEW | no | no | REI 60-A1 - D,s2-d0 /A1 | 0 | no | 0 | no | Codetext | AllplanAttributes - Ortscode_Geschoßbezeichnung: E02; ash_W_Trockenbau_Qualitäten: 20; Sicherheitsklasse: -
 | H2 Ebene +2 | WI-LB | 1213Wa 0812969901 | yes | Codetext | m² | Trockenbauarbeiten | Wand | Innenwand 1-Schalig | WI-LB | 0 | A | 7.5 | 1213HWa0812969832 | NEW | no | no | REI 60-A1 - D,s2-d0 /A1 | 0 | no | 0 | no | Codetext | AllplanAttributes - Ortscode_Geschoßbezeichnung: E02; ash_W_Trockenbau_Qualitäten: 9
 | H2 Ebene +2 | WI-STB | 1213Wa 0812971202 | yes | Codetext | m² | Zimmer- und Holzbauarbeiten | Wand | Innenwand 1-Schalig | WI-STB | 0 | A | 7.5 | 1213HWa0812969832 | NEW | yes | no | REI-M 60-A1 | 0 | no | 42 | no | Codetext | AllplanAttributes - Ortscode_Geschoßbezeichnung: E02
 | H2 Ebene +2 | WI-HW 60 | 1213Wa 0812985898 | yes | Codetext | m² | Zimmer- und Holzbauarbeiten | Wand | Innenwand 1-Schalig | WI-HW 60 | 0 | A | 7.5 | 1213HWa0812968155 | NEW | yes | no | REI 60-A1 - D,s2-d0 +A1 | 0 | no | 42 | no | Codetext | AllplanAttributes - Ortscode_Geschoßbezeichnung: E02; Sicherheitsklasse: -; ash W_laufende Nr. Statik: 7 (W 6.0-1)
 | H2 Ebene +2 | WI-LB | 1213Wa 0813192706 | yes | Codetext | m² | Trockenbauarbeiten | Wand | Innenwand 1-Schalig | WI-LB | 0 | A | 7.5 | 1113HWa0812553533 | NEW | no | no | REI 60-A1 - D,s2-d0 /A1 | 0 | no | 42 | no | Codetext | AllplanAttributes - Ortscode_Geschoßbezeichnung: E02; ash_W_Trockenbau_Qualitäten: 16; Sicherheitsklasse: -
 | H2 Ebene +2 | WI-LB | 1213Wa 0812970645 | yes | Codetext | m² | Trockenbauarbeiten | Wand | Innenwand 1-Schalig | WI-LB | 0 | A | 7.5 | 1213HWa0812968181 | NEW | no | no | 0 | 0 | no | 47 | no | Codetext | AllplanAttributes - Ortscode_Geschoßbezeichnung: E02; W_Deckenanschluss: Gleitender Deckenanschluss Fall 01; ash_W_Trockenbau_Qualitäten: 17; Sicherheitsklasse: -
 | H2 Ebene +2 | Installationsraum | 1213Wa 0813083886 | yes | Codetext | m² | Trockenbauarbeiten | Wand | Innenwand 1-Schalig | Installationsraum | 0 | A | 7.5 | 1213HWa0812968181 | NEW | no | no | 0 | 0 | no | 0 | no | Codetext | AllplanAttributes - Ortscode_Geschoßbezeichnung: E02; Sicherheitsklasse: -
 | H2 Ebene +2 | WI-HW 60 | 1213Wa 0813196046 | yes | Codetext | m² | Zimmer- und Holzbauarbeiten | Wand | Innenwand 1-Schalig | WI-HW 60 | 0 | A | 7.5 | 1213HWa0812968181 | NEW | no | no | 0 | 0 | no | 47 | no | Codetext | AllplanAttributes - Ortscode_Geschoßbezeichnung: E02; Sicherheitsklasse: -; ash W_laufende Nr. Statik: 3 (W 3.0)
 | H2 Ebene +2 | WI-IW | 1213Wa 0813196047 | yes | Codetext | m² | Trockenbauarbeiten | Wand | Innenwand 1-Schalig | WI-IW | 0 | A | 7.5 | 1213HWa0812968181 | NEW | no | no | 0 | 0 | no | 0 | no | Codetext | AllplanAttributes - Ortscode_Geschoßbezeichnung: E02; ash_W_Trockenbau_Qualitäten: 17; Sicherheitsklasse: -
 | H2 Ebene +2 | WI-LB | 1213Wa 0812970081 | yes | Codetext | m² | Trockenbauarbeiten | Wand | Innenwand 1-Schalig | WI-LB | 0 | A | 7.5 | 1213HWa0812968180 | NEW | no | no | 0 | 0 | no | 47 | no | Codetext | AllplanAttributes - Ortscode_Geschoßbezeichnung: E02; ash_W_Trockenbau_Qualitäten: 7; Sicherheitsklasse: -
 | H2 Ebene +2 | WI-HW 60 | 1213Wa 0813083846 | yes | Codetext | m² | Zimmer- und Holzbauarbeiten | Wand | Innenwand 1-Schalig | WI-HW 60 | 0 | A | 7.5 | 1213HWa0812968180 | NEW | no | no | 0 | 0 | no | 47 | no | Codetext | AllplanAttributes - Ortscode_Geschoßbezeichnung: E02; Sicherheitsklasse: -; ash W_laufende Nr. Statik: 3 (W 3.0)
 | H2 Ebene +2 | WI-LW 60 | 1213Wa 0813457907 | yes |  | m² | Trockenbauarbeiten | Wand | Innenwand 1-Schalig | WI-LW 60 |  |  | 7.5 | 1213HWa0812968106 | NEW | no | no | 0 | AllplanAttributes - Ortscode_Geschoßbezeichnung: E02; W_Deckenanschluss: Gleitender Deckenanschluss Fall 01; ash_W_Trockenbau_Qualitäten: 12c
 | H2 Ebene +2 | WI-LB | 1213Wa 0813706115 | yes | Codetext | m² | Trockenbauarbeiten | Wand | Innenwand 1-Schalig | WI-LB | 0 | A | 7.5 | 1213HWa0812968153 | NEW | no | no | - | 0 | no |  | no | Codetext | AllplanAttributes - Ortscode_Geschoßbezeichnung: E02; ash_W_Trockenbau_Qualitäten: 9
 | H2 Ebene +2 | WI-STB | 1213Wa 0813706113 | yes | Codetext | m² | Betonarbeiten | Wand | Innenwand 1-Schalig | WI-STB | 0 | A | 7.5 | 1213HWa0812968153 | NEW | yes | no | - | 0 | no | 42 | no | Codetext | AllplanAttributes - Ortscode_Geschoßbezeichnung: E02
 | H2 Ebene +2 | WI-LB | 1213Wa 0813706112 | yes | Codetext | m² | Trockenbauarbeiten | Wand | Innenwand 1-Schalig | WI-LB | 0 | A | 7.5 | 1213HWa0812968153 | NEW | no | no | - | 0 | no |  | no | Codetext | AllplanAttributes - Ortscode_Geschoßbezeichnung: E02; ash_W_Trockenbau_Qualitäten: 9
 | H2 Ebene +2 | WI-LB | 1213Wa 0812986013 | yes | Codetext | m² | Trockenbauarbeiten | Wand | Innenwand 1-Schalig | WI-LB | 0 | A | 7.5 | 1213HWa0812968267 | NEW | no | no | 0 | 0 | no | 0 | no | Codetext | AllplanAttributes - Ortscode_Geschoßbezeichnung: E02; W_Deckenanschluss: Gleitender Deckenanschluss Fall 01; ash_W_Trockenbau_Qualitäten: 12a
 | H2 Ebene +2 | WI-LB | 1213Wa 0812970948 | yes | Codetext | m² | Trockenbauarbeiten | Wand | Innenwand 1-Schalig | WI-LB | 0 | A | 7.5 | 1213HWa0812968196 | NEW |  | no | REI 60-A1 - D,s2-d0 +A1 | 0 | no | 0 | no | Codetext | AllplanAttributes - Ortscode_Geschoßbezeichnung: E02; W_Deckenanschluss: Gleitender Deckenanschluss Fall 01; ash_W_Trockenbau_Qualitäten: 10b
 | H2 Ebene +2 | WI-LB | 1213Wa 0812970924 | yes | Codetext | m² | Trockenbauarbeiten | Wand | Innenwand 1-Schalig | WI-LB | 0 | A | 7.5 | 1213HWa0812968113 | NEW | no | no | REI 60-A1 - D,s2-d0 +A1 | 0 | no | 47 | no | Codetext | AllplanAttributes - Ortscode_Geschoßbezeichnung: E02; W_Deckenanschluss: Gleitender Deckenanschluss Fall 01; ash_W_Trockenbau_Qualitäten: 1b
 | H2 Ebene +2 | WI-LB | 1213Wa 0813137593 | yes | Codetext | m² | Trockenbauarbeiten | Wand | Innenwand 1-Schalig | WI-LB | 0 | A | 7.5 | 1213HWa0813137248 | NEW | no | no | REI 60-A1 - D,s2-d0 /A1 | 0 | no | 0 | no | Codetext | AllplanAttributes - Ortscode_Geschoßbezeichnung: E02; W_Deckenanschluss: Gleitender Deckenanschluss Fall 01; ash_W_Trockenbau_Qualitäten: 12b
 | H2 Ebene +2 | WI-LB | 1213Wa 0812970448 | yes | Codetext | m² | Trockenbauarbeiten | Wand | Innenwand 1-Schalig | WI-LB | 0 | A | 7.5 | 1213HWa0812968448 | NEW | no | no | REI 60-A1 - D,s2-d0 /A1 | 0 | no | 0 | no | Codetext | AllplanAttributes - Ortscode_Geschoßbezeichnung: E02; ash_W_Trockenbau_Qualitäten: 9
 | H2 Ebene +2 | WI-HW 60 | 1213Wa 0812986275 | yes | Codetext | m² | Zimmer- und Holzbauarbeiten | Wand | Innenwand 1-Schalig | WI-HW 60 | 0 | A | 7.5 | 1213HWa0812968119 | NEW | no | no | 0 | 0 | no | 47 | no | Codetext | AllplanAttributes - Ortscode_Geschoßbezeichnung: E02; Sicherheitsklasse: -; ash W_laufende Nr. Statik: 3 (W 3.0)
 | H2 Ebene +2 | Installationsraum | 1213Wa 0813085084 | yes | Codetext | m² | Trockenbauarbeiten | Wand | Innenwand 1-Schalig | Installationsraum | 0 | A | 7.5 | 1213HWa0812968119 | NEW | no | no | 0 | 0 | no | 0 | no | Codetext | AllplanAttributes - Ortscode_Geschoßbezeichnung: E02; Sicherheitsklasse: -
 | H2 Ebene +2 | WI-LB | 1213Wa 0813097591 | yes | Codetext | m² | Trockenbauarbeiten | Wand | Innenwand 1-Schalig | WI-LB | 0 | A | 7.5 | 1213HWa0812968119 | NEW | no | no | 0 | 0 | no | 47 | no | Codetext | AllplanAttributes - Ortscode_Geschoßbezeichnung: E02; ash_W_Trockenbau_Qualitäten: 8; Sicherheitsklasse: -
 | H2 Ebene +2 | Installationsraum | 1213Wa 0812970568 | yes | Codetext | m² | Trockenbauarbeiten | Wand | Installationswand | Installationsraum | 0 | A | 7.5 | 1213HWa0812968427 | NEW | no | no | 0 | 0 | no | 0 | no | Codetext | AllplanAttributes - Ortscode_Geschoßbezeichnung: E02
 | H2 Ebene +2 | WI-VS | 1213Wa 0812970566 | yes | Codetext | m² | Trockenbauarbeiten | Wand | Installationswand | WI-VS | 0 | A | 7.5 | 1213HWa0812968427 | NEW | no | no | 0 | 0 | no | 0 | no | Codetext | AllplanAttributes - Ortscode_Geschoßbezeichnung: E02; W_Deckenanschluss: Gleitender Deckenanschluss Fall 03; ash_W_Trockenbau_Qualitäten: 21
 | H2 Ebene +2 | WI-LB | 1213Wa 0813167303 | yes | Codetext | m² | Trockenbauarbeiten | Wand | Innenwand 1-Schalig | WI-LB | 0 | A | 7.5 | 1213HWa0813167250 | NEW | no | no | 0 | 0 | no | 0 | no | Codetext | AllplanAttributes - Ortscode_Geschoßbezeichnung: E02; W_Deckenanschluss: Gleitender Deckenanschluss Fall 01; ash_W_Trockenbau_Qualitäten: 12a
 | H2 Ebene +2 | Installationsraum | 1213Wa 0813718837 | yes | Codetext | m² | Trockenbauarbeiten | Wand | Installationswand | Installationsraum | 0 | A | 7.5 | 1163HWa0812463423 | NEW | no | no | 0 | 0 | no | 0 | no | Codetext | AllplanAttributes - Ortscode_Geschoßbezeichnung: E02; Positionsnummer_Text: U100
 | H2 Ebene +2 | WI-VS | 1213Wa 0813718839 | yes | Codetext | m² | Trockenbauarbeiten | Wand | Installationswand | WI-VS | 0 | A | 7.5 | 1163HWa0812463423 | NEW | no | no | 0 | 0 | no |  | no | Codetext | AllplanAttributes - Ortscode_Geschoßbezeichnung: E02; W_Deckenanschluss: Gleitender Deckenanschluss Fall 01; Positionsnummer_Text: U100
 | H2 Ebene +2 | WI-IW | 1213Wa 0813641977 | yes | Codetext | m² | Trockenbauarbeiten | Wand | Installationswand | WI-IW | 0 | A | 7.5 | 1213HWa0812968250 | NEW | no | no | 0 | 0 | no |  | no | Codetext | AllplanAttributes - Ortscode_Geschoßbezeichnung: E02; W_Deckenanschluss: Gleitender Deckenanschluss Fall 01; ash_W_Trockenbau_Qualitäten: 11
 | H2 Ebene +2 | Installationsraum | 1213Wa 0813641978 | yes | Codetext | m² | Trockenbauarbeiten | Wand | Installationswand | Installationsraum | 0 | A | 7.5 | 1213HWa0812968250 | NEW | no | no | 0 | 0 | no | 0 | no | Codetext | AllplanAttributes - Ortscode_Geschoßbezeichnung: E02
 | H2 Ebene +2 | WI-IW | 1213Wa 0813641979 | yes | Codetext | m² | Trockenbauarbeiten | Wand | Installationswand | WI-IW | 0 | A | 7.5 | 1213HWa0812968250 | NEW | no | no | 0 | 0 | no |  | no | Codetext | AllplanAttributes - Ortscode_Geschoßbezeichnung: E02; W_Deckenanschluss: Gleitender Deckenanschluss Fall 01; ash_W_Trockenbau_Qualitäten: 11
 | H2 Ebene +2 | WI-LB | 1213Wa 0812985975 | yes | Codetext | m² | Trockenbauarbeiten | Wand | Innenwand 1-Schalig | WI-LB | 0 | A | 7.5 | 1213HWa0812968532 | NEW | no | no | REI 60-A1 - D,s2-d0 /A1 | 0 | no | 0 | no | Codetext | AllplanAttributes - Ortscode_Geschoßbezeichnung: E02; ash_W_Trockenbau_Qualitäten: 16
 | H2 Ebene +2 | WI-HW 60 | 1213Wa 0813196706 | yes | Codetext | m² | Zimmer- und Holzbauarbeiten | Wand | Innenwand 1-Schalig | WI-HW 60 | 0 | A | 7.5 | 1213HWa0812968532 | NEW | no | no | REI 60-A1 - D,s2-d0 /A1 | 0 | no | 0 | no | Codetext | AllplanAttributes - Ortscode_Geschoßbezeichnung: E02; ash W_laufende Nr. Statik: 3 (W 3.0)
 | H2 Ebene +2 | WI-LB | 1213Wa 0812986400 | yes | Codetext | m² | Trockenbauarbeiten | Wand | Innenwand 1-Schalig | WI-LB | 0 | A | 7.5 | 1213HWa0813192446 | NEW | no | no | REI 60-A1 - D,s2-d0 /A1 | 0 | no | 0 | no | Codetext | AllplanAttributes - Ortscode_Geschoßbezeichnung: E02; ash_W_Trockenbau_Qualitäten: 6
 | H2 Ebene +2 | WI-HW 60 | 1213Wa 0813207678 | yes |  | m² | Zimmer- und Holzbauarbeiten | Wand | Innenwand 1-Schalig | WI-HW 60 |  |  | 7.5 | 1213HWa0812969865 | NEW | no | no | REI-M 60-D,s2,d0 + A1 |  |  | 0 | AllplanAttributes - Ortscode_Geschoßbezeichnung: E02; ash W_laufende Nr. Statik: 7 (W 6.0-1)
 | H2 Ebene +2 | WI-LB | 1213Wa 0813496809 | yes | Codetext | m² | Trockenbauarbeiten | Wand | Innenwand 1-Schalig | WI-LB | 0 | A | 7.5 | 1113HWa0812553533 | NEW | no | no | REI 60-A1 - D,s2-d0 /A1 | 0 | no | 0 | no | Codetext | AllplanAttributes - Ortscode_Geschoßbezeichnung: E02; ash_W_Trockenbau_Qualitäten: 16; Sicherheitsklasse: -
 | H2 Ebene +2 | WI-HW 60 | 1213Wa 0813641525 | yes | Codetext | m² | Zimmer- und Holzbauarbeiten | Wand | Innenwand 1-Schalig | WI-HW 60 | 0 | A | 7.5 | 1213HWa0812968238 | NEW | no | no | REI 30 | 0 | no |  | no | Codetext | AllplanAttributes - Ortscode_Geschoßbezeichnung: E02; Sicherheitsklasse: -; ash W_laufende Nr. Statik: 1 (W 1.0/ 1.1/ 1.2)
 | H2 Ebene +2 | WI-LB | 1213Wa 0813644086 | yes | Codetext | m² | Trockenbauarbeiten | Wand | Innenwand 1-Schalig | WI-LB | 0 | A | 7.5 | 1213HWa0812968082 | NEW |  | no | 0 | 0 | no |  | no | Codetext | AllplanAttributes - Ortscode_Geschoßbezeichnung: E02; W_Deckenanschluss: Gleitender Deckenanschluss Fall 01; ash_W_Trockenbau_Qualitäten: 1
 | H2 Ebene +2 | WI-STB | 1213Wa 0812970358 | yes | Codetext | m² | Zimmer- und Holzbauarbeiten | Wand | Außenwand 1-Schalig | WI-STB | 0 | A | 7.5 | 1213HWa0812968538 | NEW | yes | no | REI 60-A1 - D,s2-d0 /A1 | 0 | no | 52 | no | Codetext | AllplanAttributes - Ortscode_Geschoßbezeichnung: E02
 | H2 Ebene +2 | WI-LB | 1213Wa 0812970355 | yes | Codetext | m² | Trockenbauarbeiten | Wand | Außenwand 1-Schalig | WI-LB | 0 | A | 7.5 | 1213HWa0812968538 | NEW | no | no | REI 60-A1 - D,s2-d0 /A1 | 0 | no |  | no | Codetext | AllplanAttributes - Ortscode_Geschoßbezeichnung: E02; ash_W_Trockenbau_Qualitäten: 9
 | H2 Ebene +2 | WI-STB | 1213Wa 0812986381 | yes | Codetext | m² | Zimmer- und Holzbauarbeiten | Wand | Innenwand 1-Schalig | WI-STB | 0 | A | 7.5 | 1213HWa0812969822 | NEW | yes | no | REI 60-A1 - D,s2-d0 /A1 | 0 | no | 0 | no | Codetext | AllplanAttributes - Ortscode_Geschoßbezeichnung: E02
 | H2 Ebene +2 | WI-LB | 1213Wa 0812986375 | yes | Codetext | m² | Trockenbauarbeiten | Wand | Innenwand 1-Schalig | WI-LB | 0 | A | 7.5 | 1213HWa0812969822 | NEW | no | no | REI 60-A1 - D,s2-d0 /A1 | 0 | no | 0 | no | Codetext | AllplanAttributes - Ortscode_Geschoßbezeichnung: E02; ash_W_Trockenbau_Qualitäten: 16
im Zusammenhang mit der Möblierung anzufertigen | H2 Ebene +2 | WI-LB | 1213Wa 0813692093 | yes | Codetext | m² | Trockenbauarbeiten | Wand | im Zusammenhang mit der Möblierung anzufertigen | WI-LB | 0 | A | 7.5 |  | NEW | no | no | 0 | 0 | no | 47 | no | Codetext | AllplanAttributes - Ortscode_Geschoßbezeichnung: E02; W_Deckenanschluss: Gleitender Deckenanschluss Fall 01; ash_W_Trockenbau_Qualitäten: 1b
im Zusammenhang mit der Möblierung anzufertigen | H2 Ebene +2 | WI-LB | 1213Wa 0813728731 | yes | Codetext | m² | Trockenbauarbeiten | Wand | im Zusammenhang mit der Möblierung anzufertigen | WI-LB | 0 | A | 7.5 |  | NEW | no | no | 0 | 0 | no | 0 | no | Codetext | AllplanAttributes - Ortscode_Geschoßbezeichnung: E02; W_Deckenanschluss: Gleitender Deckenanschluss Fall 01; ash_W_Trockenbau_Qualitäten: 1b
im Zusammenhang mit der Möblierung anzufertigen | H2 Ebene +2 | WI-LB | 1213Wa 0813693770 | yes | Codetext | m² | Trockenbauarbeiten | Wand | im Zusammenhang mit der Möblierung anzufertigen | WI-LB | 0 | A | 7.5 |  | NEW | no | no | 0 | 0 | no | 0 | no | Codetext | AllplanAttributes - Ortscode_Geschoßbezeichnung: E02; W_Deckenanschluss: Gleitender Deckenanschluss Fall 01; ash_W_Trockenbau_Qualitäten: 1b
im Zusammenhang mit der Möblierung anzufertigen | H2 Ebene +2 | WI-LB | 1213Wa 0813728760 | yes | Codetext | m² | Trockenbauarbeiten | Wand | im Zusammenhang mit der Möblierung anzufertigen | WI-LB | 0 | A | 7.5 |  | NEW | no | no | 0 | 0 | no | 47 | no | Codetext | AllplanAttributes - Ortscode_Geschoßbezeichnung: E02; W_Deckenanschluss: Gleitender Deckenanschluss Fall 01; ash_W_Trockenbau_Qualitäten: 1b
 | H2 Ebene +2 | WI-LB | 1213Wa 0812986171 | yes | Codetext | m² | Trockenbauarbeiten | Wand | Innenwand 1-Schalig | WI-LB | 0 | A | 7.5 | 1213HWa0812968385 | NEW |  | no | 0 | 0 | no | 52 | no | Codetext | AllplanAttributes - Ortscode_Geschoßbezeichnung: E02; W_Deckenanschluss: Gleitender Deckenanschluss Fall 01; ash_W_Trockenbau_Qualitäten: 4
 | H2 Ebene +2 | WI-HW 60 | 1213Wa 0813245905 | yes | Codetext | m² | Zimmer- und Holzbauarbeiten | Wand | Innenwand 1-Schalig | WI-HW 60 | 0 | A | 7.5 | 1213HWa0812968166 | NEW |  | no | 0 | 0 | no |  | no | Codetext | AllplanAttributes - Ortscode_Geschoßbezeichnung: E02; Sicherheitsklasse: -; ash W_laufende Nr. Statik: 1 (W 1.0/ 1.1/ 1.2)
 | H2 Ebene +2 | WI-LB | 1213Wa 0813695524 | yes | Codetext | m² | Trockenbauarbeiten | Wand | Innenwand 1-Schalig | WI-LB | 0 | A | 7.5 | 1213HWa0812968095 | NEW |  | no | 0 | 0 | no |  | no | Codetext | AllplanAttributes - Ortscode_Geschoßbezeichnung: E02; W_Deckenanschluss: Gleitender Deckenanschluss Fall 01; ash_W_Trockenbau_Qualitäten: 6
 | H2 Ebene +2 | WI-LB | 1213Wa 0813695515 | yes | Codetext | m² | Trockenbauarbeiten | Wand | Innenwand 1-Schalig | WI-LB | 0 | A | 7.5 | 1213HWa0812968095 | NEW |  | no | 0 | 0 | no |  | no | Codetext | AllplanAttributes - Ortscode_Geschoßbezeichnung: E02; W_Deckenanschluss: Gleitender Deckenanschluss Fall 01; ash_W_Trockenbau_Qualitäten: 6
 | H2 Ebene +2 | WI-HW 60 | 1213Wa 0813668182 | yes | Codetext | m² | Zimmer- und Holzbauarbeiten | Wand | Innenwand 1-Schalig | WI-HW 60 | 0 | A | 7.5 | 1213HWa0812968142 | NEW | yes | no | REI 60-A1 - D,s2-d0 /A1 | 0 | no | 47 | no | Codetext | AllplanAttributes - Ortscode_Geschoßbezeichnung: E02; ash W_laufende Nr. Statik: 1 (W 1.0/ 1.1/ 1.2)
 | H2 Ebene +2 | WI-LB | 1213Wa 0813729123 | yes | Codetext | m² | Trockenbauarbeiten | Wand | Innenwand 1-Schalig | WI-LB | 0 | A | 7.5 | 1213HWa0812968464 | NEW | no | no | REI 60-A1 - D,s2-d0 /A1 | 0 | no | 0 | no | Codetext | AllplanAttributes - Ortscode_Geschoßbezeichnung: E02; W_Deckenanschluss: Gleitender Deckenanschluss Fall 01; ash_W_Trockenbau_Qualitäten: 13
 | H2 Ebene +2 | WI-HW 60 | 1213Wa 0812986408 | yes | Codetext | m² | Zimmer- und Holzbauarbeiten | Wand | Innenwand 1-Schalig | WI-HW 60 | 0 | A | 7.5 | 1213HWa0812968156 | NEW | no | no | REI 60-A1 - D,s2-d0 +A1 | 0 | no | 47 | no | Codetext | AllplanAttributes - Ortscode_Geschoßbezeichnung: E02; Sicherheitsklasse: -; ash W_laufende Nr. Statik: 3 (W 3.0)
 | H2 Ebene +2 | Installationsraum | 1213Wa 0813086369 | yes | Codetext | m² | Trockenbauarbeiten | Wand | Innenwand 1-Schalig | Installationsraum | 0 | A | 7.5 | 1113HWa0812434427 | NEW | no | no | 0 | 0 | no |  | no | Codetext | AllplanAttributes - Ortscode_Geschoßbezeichnung: E02; Sicherheitsklasse: -
 | H2 Ebene +2 | WI-LB | 1213Wa 0813201981 | yes | Codetext | m² | Trockenbauarbeiten | Wand | Innenwand 1-Schalig | WI-LB | 0 | A | 7.5 | 1213HWa0812968156 | NEW | no | no | REI 60-A1 - D,s2-d0 /A1 | 0 | no | 47 | no | Codetext | AllplanAttributes - Ortscode_Geschoßbezeichnung: E02; ash_W_Trockenbau_Qualitäten: 6; Sicherheitsklasse: -
 | H2 Ebene +2 | WI-LB | 1213Wa 0813692677 | yes | Codetext | m² | Trockenbauarbeiten | Wand | Innenwand 1-Schalig | WI-LB | 0 | A | 7.5 | 1113HWa0812959982 | NEW | no | no | REI 60-A1 - D,s2-d0 /A1 | 0 | no | 0 | no | Codetext | AllplanAttributes - Ortscode_Geschoßbezeichnung: E02; ash_W_Trockenbau_Qualitäten: 15; Sicherheitsklasse: -
 | H2 Ebene +2 | WI-HW 60 | 1213Wa 0813692676 | yes | Codetext | m² | Zimmer- und Holzbauarbeiten | Wand | Innenwand 1-Schalig | WI-HW 60 | 0 | A | 7.5 | 1213HWa0813014022 | NEW | no | no | REI 60-A1 - D,s2-d0 +A1 | 0 | no | 47 | no | Codetext | AllplanAttributes - Ortscode_Geschoßbezeichnung: E02; Sicherheitsklasse: -; ash W_laufende Nr. Statik: 3 (W 3.0)
 | H2 Ebene +2 | Installationsraum | 1213Wa 0813692674 | yes | Codetext | m² | Trockenbauarbeiten | Wand | Innenwand 1-Schalig | Installationsraum | 0 | A | 7.5 | 1113HWa0812434427 | NEW | no | no | 0 | 0 | no |  | no | Codetext | AllplanAttributes - Ortscode_Geschoßbezeichnung: E02; Sicherheitsklasse: -
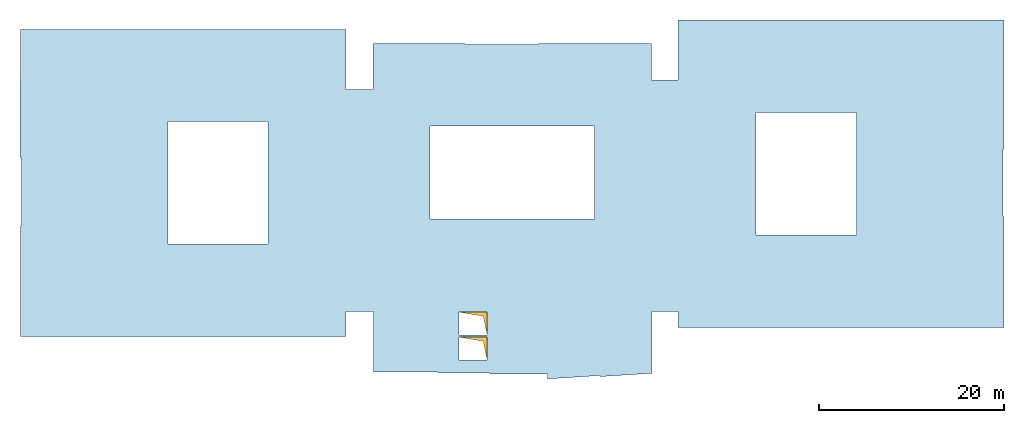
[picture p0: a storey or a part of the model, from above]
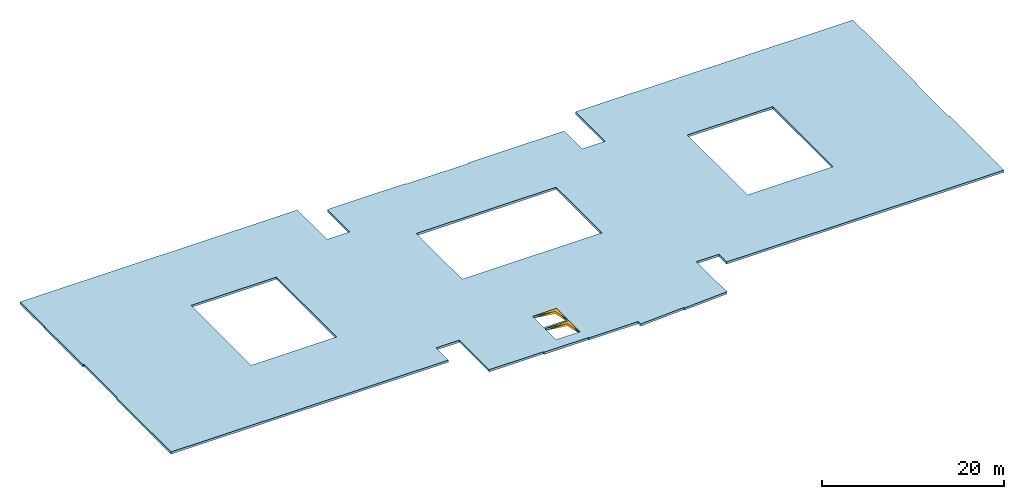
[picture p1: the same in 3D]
Properties of the parts of a building model (IFC4), part 59 of 80

# IfcWall (6826)
Name | In | Material | Allright_Bauteil_ID | 2D Interaktion | Codetext | Abrechnungsart | Gewerk | Objektname | Bezeichnung | AllplanAttributes, Material | Typ = SurfaceSpreadOfFlame | Brandschutzklasse | OKFF | P_ID | Status | LoadBearing | IsExternal | FireRating | ThermalTransmittance (W/K/m2) | Combustible | AcousticRating | Compartmentation | Reference
 | H2 Ebene +2 | WI-LB | 1213Wa 0813692673 | yes | Codetext | m² | Trockenbauarbeiten | Wand | Innenwand 1-Schalig | WI-LB | 0 | A | 7.5 | 1213HWa0813014022 | NEW | no | no | REI 60-A1 - D,s2-d0 /A1 | 0 | no | 47 | no | Codetext | AllplanAttributes - Ortscode_Geschoßbezeichnung: E02; ash_W_Trockenbau_Qualitäten: 15; Sicherheitsklasse: -
 | H2 Ebene +2 | WI-STB | 1213Wa 0812970403 | yes | Codetext | m² | Zimmer- und Holzbauarbeiten | Wand | Außenwand 1-Schalig | WI-STB | 0 | A | 7.5 | 1213HWa0812968076 | NEW | yes | no | REI 60-A1 - D,s2-d0 /A1 | 0 | no |  | no | Codetext | AllplanAttributes - Ortscode_Geschoßbezeichnung: E02
 | H2 Ebene +2 | WI-VS | 1213Wa 0813641567 | yes | Codetext | m² | Trockenbauarbeiten | Wand | Innenwand 1-Schalig | WI-VS | 0 | A | 7.5 | 1213HWa0812968098 | NEW | no | no | 0 | 0 | no |  | no | Codetext | AllplanAttributes - Ortscode_Geschoßbezeichnung: E02; W_Deckenanschluss: Gleitender Deckenanschluss Fall 01; ash_W_Trockenbau_Qualitäten: 2
 | H2 Ebene +2 | WI-LB | 1213Wa 0813746471 | yes | Codetext | m² | Trockenbauarbeiten | Wand | Innenwand 1-Schalig | WI-LB | 0 | A | 7.5 | 1213HWa0812968288 | NEW |  | no | 0 | 0 | no | 52 | no | Codetext | AllplanAttributes - Ortscode_Geschoßbezeichnung: E02; W_Deckenanschluss: Gleitender Deckenanschluss Fall 01; ash_W_Trockenbau_Qualitäten: 4
 | H2 Ebene +2 | WI-LB | 1213Wa 0812986393 | yes | Codetext | m² | Trockenbauarbeiten | Wand | Innenwand 1-Schalig | WI-LB | 0 | A | 7.5 | 1213HWa0812968154 | NEW | no | no | REI 60-A1 - D,s2-d0 /A1 | 0 | no | 0 | no | Codetext | AllplanAttributes - Ortscode_Geschoßbezeichnung: E02; ash_W_Trockenbau_Qualitäten: 6
 | H2 Ebene +2 | WI-STB | 1213Wa 0813191123 | yes | Codetext | m² | Zimmer- und Holzbauarbeiten | Wand | Innenwand 1-Schalig | WI-STB | 0 | A | 7.5 | 1213HWa0812968154 | NEW | yes | no | REI 60-A1 - D,s2-d0 /A1 | 0 | no | 0 | no | Codetext | AllplanAttributes - Ortscode_Geschoßbezeichnung: E02
 | H2 Ebene +2 | WI-LB | 1213Wa 0813751193 | yes | Codetext | m² | Trockenbauarbeiten | Wand | Innenwand 1-Schalig | WI-LB | 0 | A | 7.5 | 1213HWa0812968154 | NEW | no | no | REI 60-A1 - D,s2-d0 /A1 | 0 | no | 0 | no | Codetext | AllplanAttributes - Ortscode_Geschoßbezeichnung: E02; ash_W_Trockenbau_Qualitäten: 6
 | H2 Ebene +2 | WI-STB | 1213Wa 0813751194 | yes | Codetext | m² | Zimmer- und Holzbauarbeiten | Wand | Innenwand 1-Schalig | WI-STB | 0 | A | 7.5 | 1213HWa0812968154 | NEW | yes | no | REI 60-A1 - D,s2-d0 /A1 | 0 | no | 0 | no | Codetext | AllplanAttributes - Ortscode_Geschoßbezeichnung: E02
 | H2 Ebene +2 | WI-LB | 1213Wa 0813751265 | yes | Codetext | m² | Trockenbauarbeiten | Wand | Innenwand 1-Schalig | WI-LB | 0 | A | 7.5 | 1213HWa0812968154 | NEW | no | no | REI 60-A1 - D,s2-d0 /A1 | 0 | no | 0 | no | Codetext | AllplanAttributes - Ortscode_Geschoßbezeichnung: E02; ash_W_Trockenbau_Qualitäten: 9
 | H2 Ebene +1 | WI-HW 60 | 1155Wa 0000010292 | yes | Codetext | m² | Zimmer- und Holzbauarbeiten | Wand | Innenwand 1-Schalig | WI-HW 60 | 0 | A | 3.75 | 1155HWa0000010286 | NEW | yes | no | 0 | 0.9 | no | 32 | no | Codetext | AllplanAttributes - Sicherheitsklasse: -; Sonnenschutztyp: Movable; g-Wert: 0,51
 | H2 Ebene +1 | WA-LB | 1155Wa 0000193729 | yes |  | m² | Trockenbauarbeiten | Wand | Außenwand 7-Schalig | WA-LB |  |  | 3.75 | 1155HWa0000193728 | NEW |  | yes | 0 | 0.9 |  | 32 | AllplanAttributes - Sicherheitsklasse: -; Sonnenschutztyp: Movable; g-Wert: 0,51
2x Gipsfaserplatte | H2 Ebene +1 | WA-LB | 1155Wa 0813754323 | yes |  | m² | Trockenbauarbeiten | Wand | 2x Gipsfaserplatte | WA-LB |  |  | 3.75 | 1105HWa0811567714 | NEW | no |  | 0 | AllplanAttributes - Ortscode_Geschoßbezeichnung: E00; Sicherheitsklasse: -; Positionsnummer_Text: U23
 | H2 Ebene +1 | WA-LB | 1155Wa 0000200300 | yes |  | m² | Trockenbauarbeiten | Wand | Außenwand 7-Schalig | WA-LB |  |  | 3.75 | 1155HWa0000200299 | NEW |  | yes | 0 | 0.9 |  | 32 | AllplanAttributes - Sicherheitsklasse: -; Sonnenschutztyp: Movable; g-Wert: 0,51
2x Gipsfaserplatte | H2 Ebene +1 | WA-LB | 1155Wa 0813754116 | yes |  | m² | Trockenbauarbeiten | Wand | 2x Gipsfaserplatte | WA-LB |  |  | 3.75 | 1105HWa0811567249 | NEW | no | yes | 0 | AllplanAttributes - Ortscode_Geschoßbezeichnung: E00; Sicherheitsklasse: -; Positionsnummer_Text: U23
Holzständer + Zwischendämmung | H2 Ebene +1 | WA-HD | 1155Wa 0813754301 | yes |  | m³ | Zimmer- und Holzbauarbeiten | Wand | Holzständer + Zwischendämmung | WA-HD |  |  | 3.75 | 1105HWa0811567249 | NEW | yes | yes | 0 | AllplanAttributes - Ortscode_Geschoßbezeichnung: E00; ash D_Detailverweis: DT D; ash D_Plannummer: D1851; Sicherheitsklasse: -; ash W_laufende Nr. Statik: 5 (W 4.0); Positionsnummer_Text: U23
Staffel + Zwischendämmung | H2 Ebene +1 | WA-DL | 1155Wa 0813754321 | yes |  | m³ | Zimmer- und Holzbauarbeiten | Wand | Staffel + Zwischendämmung | WA-DL |  |  | 3.75 | 1105HWa0811567249 | NEW | no | yes | 0 | AllplanAttributes - Ortscode_Geschoßbezeichnung: E00; Sicherheitsklasse: -; Positionsnummer_Text: U23
nichtbrennbare Trägerplatte | H2 Ebene +1 | WA-TP | 1155Wa 0813754316 | yes |  | m² | Trockenbauarbeiten | Wand | nichtbrennbare Trägerplatte | WA-TP |  |  | 3.75 | 1105HWa0811567249 | NEW | no | yes | 0 | AllplanAttributes - Ortscode_Geschoßbezeichnung: E00; Sicherheitsklasse: -; Positionsnummer_Text: U23
Konterlattung | H2 Ebene +1 | WA-KL | 1155Wa 0813754312 | yes |  | m² | Zimmer- und Holzbauarbeiten | Wand | Konterlattung | WA-KL |  |  | 3.75 | 1105HWa0811567249 | NEW | no | yes | 0 | AllplanAttributes - Ortscode_Geschoßbezeichnung: E00; Sicherheitsklasse: -; Positionsnummer_Text: U23
Traglattung | H2 Ebene +1 | WA-TL | 1155Wa 0813754308 | yes |  | m² | Zimmer- und Holzbauarbeiten | Wand | Traglattung | WA-TL |  |  | 3.75 | 1105HWa0811567249 | NEW | no | yes | 0 | AllplanAttributes - Ortscode_Geschoßbezeichnung: E00; Sicherheitsklasse: -; Positionsnummer_Text: U23
Keramikschindel | H2 Ebene +1 | WA-HS | 1155Wa 0813754305 | yes |  | m² | Zimmer- und Holzbauarbeiten | Wand | Keramikschindel | WA-HS |  |  | 3.75 | 1105HWa0811567249 | NEW | no | yes | 0 | AllplanAttributes - Ortscode_Geschoßbezeichnung: E00; Sicherheitsklasse: -; Positionsnummer_Text: U23
2x Gipsfaserplatte | H2 Ebene +1 | WA-LB | 1155Wa 0813754295 | yes |  | m² | Trockenbauarbeiten | Wand | 2x Gipsfaserplatte | WA-LB |  |  | 3.75 | 1105HWa0811567713 | NEW | no | yes | REI-M 60-D,s2,d0 + A1 | AllplanAttributes - Ortscode_Geschoßbezeichnung: E00; Sicherheitsklasse: -; Positionsnummer_Text: U23
Holzwerkstoffplatte | H2 Ebene +1 | WA-LB | 1155Wa 0813754291 | yes |  | m³ | Trockenbauarbeiten | Wand | Holzwerkstoffplatte | WA-LB |  |  | 3.75 | 1105HWa0811567713 | NEW | yes | yes | REI-M 60-D,s2,d0 + A1 | AllplanAttributes - Ortscode_Geschoßbezeichnung: E00; Sicherheitsklasse: -; Positionsnummer_Text: U23
Holzständer + Zwischendämmung | H2 Ebene +1 | WA-HD | 1155Wa 0813754260 | yes |  | m³ | Zimmer- und Holzbauarbeiten | Wand | Holzständer + Zwischendämmung | WA-HD |  |  | 3.75 | 1105HWa0811567713 | NEW | yes | yes | REI-M 60-D,s2,d0 + A1 | AllplanAttributes - Ortscode_Geschoßbezeichnung: E00; ash D_Detailverweis: DT A; ash D_Plannummer: D1850; Sicherheitsklasse: -; ash W_laufende Nr. Statik: 6 (W 6.0); Positionsnummer_Text: U23
Holzwerkstoffplatte | H2 Ebene +1 | WA-LB | 1155Wa 0813754287 | yes |  | m³ | Trockenbauarbeiten | Wand | Holzwerkstoffplatte | WA-LB |  |  | 3.75 | 1105HWa0811567713 | NEW | yes | yes | REI-M 60-D,s2,d0 + A1 | AllplanAttributes - Ortscode_Geschoßbezeichnung: E00; Sicherheitsklasse: -; Positionsnummer_Text: U23
nichtbrennbare Trägerplatte | H2 Ebene +1 | WA-TP | 1155Wa 0813754283 | yes |  | m² | Trockenbauarbeiten | Wand | nichtbrennbare Trägerplatte | WA-TP |  |  | 3.75 | 1105HWa0811567713 | NEW | no | yes | REI-M 60-D,s2,d0 + A1 | AllplanAttributes - Ortscode_Geschoßbezeichnung: E00; Sicherheitsklasse: -; Positionsnummer_Text: U23
Staffel + Zwischendämmung | H2 Ebene +1 | WA-DL | 1155Wa 0813754278 | yes |  | m³ | Zimmer- und Holzbauarbeiten | Wand | Staffel + Zwischendämmung | WA-DL |  |  | 3.75 | 1105HWa0811567713 | NEW | no | yes | REI-M 60-D,s2,d0 + A1 | AllplanAttributes - Ortscode_Geschoßbezeichnung: E00; Sicherheitsklasse: -; Positionsnummer_Text: U23
Konterlattung | H2 Ebene +1 | WA-KL | 1155Wa 0813754273 | yes |  | m² | Zimmer- und Holzbauarbeiten | Wand | Konterlattung | WA-KL |  |  | 3.75 | 1105HWa0811567713 | NEW | no | yes | REI-M 60-D,s2,d0 + A1 | AllplanAttributes - Ortscode_Geschoßbezeichnung: E00; Sicherheitsklasse: -; Positionsnummer_Text: U23
Traglattung | H2 Ebene +1 | WA-TL | 1155Wa 0813754269 | yes |  | m² | Zimmer- und Holzbauarbeiten | Wand | Traglattung | WA-TL |  |  | 3.75 | 1105HWa0811567713 | NEW | no | yes | REI-M 60-D,s2,d0 + A1 | AllplanAttributes - Ortscode_Geschoßbezeichnung: E00; Sicherheitsklasse: -; Positionsnummer_Text: U23
Keramikschindel | H2 Ebene +1 | WA-HS | 1155Wa 0813754265 | yes |  | m² | Zimmer- und Holzbauarbeiten | Wand | Keramikschindel | WA-HS |  |  | 3.75 | 1105HWa0811567713 | NEW | no | yes | REI-M 60-D,s2,d0 + A1 | AllplanAttributes - Ortscode_Geschoßbezeichnung: E00; Sicherheitsklasse: -; Positionsnummer_Text: U23
 | H2 Ebene +1 | WA-LB | 1155Wa 0813754101 | yes | Codetext | m² | Trockenbauarbeiten | Wand | Außenwand 7-Schalig | WA-LB | 0 | A | 3.75 | 1105HWa0000001927 | NEW | no | yes | 0 | 0 | no | 0 | no | Codetext | AllplanAttributes - Ortscode_Geschoßbezeichnung: E00; Sicherheitsklasse: -; Positionsnummer_Text: U23
 | H2 Ebene +1 | WA-HD | 1155Wa 0813754119 | yes | Codetext | m³ | Zimmer- und Holzbauarbeiten | Wand | Außenwand 7-Schalig | WA-HD | 0 | A | 3.75 | 1105HWa0000001927 | NEW | yes | yes | 0 | 0 | no | 0 | no | Codetext | AllplanAttributes - Ortscode_Geschoßbezeichnung: E00; ash D_Detailverweis: DT C/D; ash D_Plannummer: D1851; Sicherheitsklasse: -; ash W_laufende Nr. Statik: 5 (W 4.0); Positionsnummer_Text: U23
 | H2 Ebene +1 | WA-DL | 1155Wa 0813754103 | yes | Codetext | m³ | Zimmer- und Holzbauarbeiten | Wand | Außenwand 7-Schalig | WA-DL | 0 | A | 3.75 | 1105HWa0000001927 | NEW | no | yes | 0 | 0 | no | 0 | no | Codetext | AllplanAttributes - Ortscode_Geschoßbezeichnung: E00; Sicherheitsklasse: -; Positionsnummer_Text: U23
 | H2 Ebene +1 | WA-LB | 1155Wa 0813754105 | yes | Codetext | m² | Trockenbauarbeiten | Wand | Außenwand 7-Schalig | WA-LB | 0 | A | 3.75 | 1105HWa0000001927 | NEW | no | yes | 0 | 0 | no | 0 | no | Codetext | AllplanAttributes - Ortscode_Geschoßbezeichnung: E00; Sicherheitsklasse: -; Positionsnummer_Text: U23
 | H2 Ebene +1 | WA-KL | 1155Wa 0813754107 | yes | Codetext | m² | Zimmer- und Holzbauarbeiten | Wand | Außenwand 7-Schalig | WA-KL | 0 | A | 3.75 | 1105HWa0000001927 | NEW | no | yes | 0 | 0 | no | 0 | no | Codetext | AllplanAttributes - Ortscode_Geschoßbezeichnung: E00; Sicherheitsklasse: -; Positionsnummer_Text: U23
 | H2 Ebene +1 | WA-TL | 1155Wa 0813754109 | yes | Codetext | m² | Zimmer- und Holzbauarbeiten | Wand | Außenwand 7-Schalig | WA-TL | 0 | A | 3.75 | 1105HWa0000001927 | NEW | no | yes | 0 | 0 | no | 0 | no | Codetext | AllplanAttributes - Ortscode_Geschoßbezeichnung: E00; Sicherheitsklasse: -; Positionsnummer_Text: U23
Keramikschindel | H2 Ebene +1 | WA-HS | 1155Wa 0813754111 | yes | Codetext | m² | Zimmer- und Holzbauarbeiten | Wand | Keramikschindel | WA-HS | 0 | A | 3.75 | 1105HWa0000001927 | NEW | no | yes | 0 | 0 | no | 0 | no | Codetext | AllplanAttributes - Ortscode_Geschoßbezeichnung: E00; Sicherheitsklasse: -; Positionsnummer_Text: U23
 | H2 Ebene +1 | WI-LB | 1155Wa 2005705936 | yes | Codetext | m² | Trockenbauarbeiten | Wand | Innenwand 1-Schalig | WI-LB | 0 | A | 3.75 | 1163HWa0812447232 | NEW |  | no | 0 | 0 | no | 42 | no | Codetext | AllplanAttributes - Sicherheitsklasse: -; Positionsnummer_Text: U100
 | H2 Ebene +1 | WA-LB | 1155Wa 0000003844 | yes | Codetext | m² | Trockenbauarbeiten | Wand | Außenwand 7-Schalig | WA-LB | 0 | A | 3.75 | 1155HWa0000003166 | NEW | no | yes | 0 | 0.9 | no | 32 | no | Codetext | AllplanAttributes - Sicherheitsklasse: -; Sonnenschutztyp: Movable; g-Wert: 0,51
 | H2 Ebene +1 | WA-DL | 1155Wa 0000003834 | yes | Codetext | m³ | Zimmer- und Holzbauarbeiten | Wand | Außenwand 7-Schalig | WA-DL | 0 | A | 3.75 | 1155HWa0000003166 | NEW | no | yes | 0 | 0.9 | no | 32 | no | Codetext | AllplanAttributes - ash D_Detailverweis: DT D; ash D_Plannummer: D1851; Sicherheitsklasse: -; Sonnenschutztyp: Movable; g-Wert: 0,51; ash W_laufende Nr. Statik: 2 (W 2.0/ 2.1/ 2.2)
 | H2 Ebene +1 | WA-DL | 1155Wa 0000003824 | yes | Codetext | m³ | Zimmer- und Holzbauarbeiten | Wand | Außenwand 7-Schalig | WA-DL | 0 | A | 3.75 | 1155HWa0000003166 | NEW | no | yes | 0 | 0.9 | no | 32 | no | Codetext | AllplanAttributes - Sicherheitsklasse: -; Sonnenschutztyp: Movable; g-Wert: 0,51
 | H2 Ebene +1 | WA-LB | 1155Wa 0000003814 | yes | Codetext | m² | Trockenbauarbeiten | Wand | Außenwand 7-Schalig | WA-LB | 0 | A | 3.75 | 1155HWa0000003166 | NEW | no | yes | 0 | 0.9 | no | 32 | no | Codetext | AllplanAttributes - Sicherheitsklasse: -; Sonnenschutztyp: Movable; g-Wert: 0,51
 | H2 Ebene +1 | WA-KL | 1155Wa 0000003804 | yes | Codetext | m² | Zimmer- und Holzbauarbeiten | Wand | Außenwand 7-Schalig | WA-KL | 0 | A | 3.75 | 1155HWa0000003166 | NEW | no | yes | 0 | 0.9 | no | 32 | no | Codetext | AllplanAttributes - Sicherheitsklasse: -; Sonnenschutztyp: Movable; g-Wert: 0,51
 | H2 Ebene +1 | WA-TL | 1155Wa 0000003794 | yes | Codetext | m² | Zimmer- und Holzbauarbeiten | Wand | Außenwand 7-Schalig | WA-TL | 0 | A | 3.75 | 1155HWa0000003166 | NEW | no | yes | 0 | 0.9 | no | 32 | no | Codetext | AllplanAttributes - Sicherheitsklasse: -; Sonnenschutztyp: Movable; g-Wert: 0,51
 | H2 Ebene +1 | WA-HS | 1155Wa 0000003784 | yes | Codetext | m² | Zimmer- und Holzbauarbeiten | Wand | Außenwand 7-Schalig | WA-HS | 0 | A | 3.75 | 1155HWa0000003166 | NEW | no | yes | 0 | 0.9 | no | 32 | no | Codetext | AllplanAttributes - Sicherheitsklasse: -; Sonnenschutztyp: Movable; g-Wert: 0,51
 | H2 Ebene +1 | WA-LB | 1155Wa 0000001159 | yes | Codetext | m² | Trockenbauarbeiten | Wand | Außenwand 7-Schalig | WA-LB | 0 | A | 3.75 | 1155HWa0000000988 | NEW | no | yes | 0 | 0.9 | no | 32 | no | Codetext | AllplanAttributes - Sicherheitsklasse: -; Sonnenschutztyp: Movable; g-Wert: 0,51
 | H2 Ebene +1 | WA-HD | 1155Wa 0000001155 | yes | Codetext | m³ | Zimmer- und Holzbauarbeiten | Wand | Außenwand 7-Schalig | WA-HD | 0 | A | 3.75 | 1155HWa0000000988 | NEW | no | yes | 0 | 0.9 | no | 32 | no | Codetext | AllplanAttributes - Sicherheitsklasse: -; Sonnenschutztyp: Movable; g-Wert: 0,51; ash W_laufende Nr. Statik: 2 (W 2.0/ 2.1/ 2.2)
 | H2 Ebene +1 | WA-DL | 1155Wa 0000001135 | yes | Codetext | m³ | Zimmer- und Holzbauarbeiten | Wand | Außenwand 7-Schalig | WA-DL | 0 | A | 3.75 | 1155HWa0000000988 | NEW | no | yes | 0 | 0.9 | no | 32 | no | Codetext | AllplanAttributes - Sicherheitsklasse: -; Sonnenschutztyp: Movable; g-Wert: 0,51
 | H2 Ebene +1 | WA-LB | 1155Wa 0000001139 | yes | Codetext | m² | Trockenbauarbeiten | Wand | Außenwand 7-Schalig | WA-LB | 0 | A | 3.75 | 1155HWa0000000988 | NEW | no | yes | 0 | 0.9 | no | 32 | no | Codetext | AllplanAttributes - Sicherheitsklasse: -; Sonnenschutztyp: Movable; g-Wert: 0,51
 | H2 Ebene +1 | WA-KL | 1155Wa 0000001143 | yes | Codetext | m² | Zimmer- und Holzbauarbeiten | Wand | Außenwand 7-Schalig | WA-KL | 0 | A | 3.75 | 1155HWa0000000988 | NEW | no | yes | 0 | 0.9 | no | 32 | no | Codetext | AllplanAttributes - Sicherheitsklasse: -; Sonnenschutztyp: Movable; g-Wert: 0,51
 | H2 Ebene +1 | WA-TL | 1155Wa 0000001147 | yes | Codetext | m² | Zimmer- und Holzbauarbeiten | Wand | Außenwand 7-Schalig | WA-TL | 0 | A | 3.75 | 1155HWa0000000988 | NEW | no | yes | 0 | 0.9 | no | 32 | no | Codetext | AllplanAttributes - Sicherheitsklasse: -; Sonnenschutztyp: Movable; g-Wert: 0,51
 | H2 Ebene +1 | WA-HS | 1155Wa 0000001151 | yes | Codetext | m² | Zimmer- und Holzbauarbeiten | Wand | Außenwand 7-Schalig | WA-HS | 0 | A | 3.75 | 1155HWa0000000988 | NEW | no | yes | 0 | 0.9 | no | 32 | no | Codetext | AllplanAttributes - Sicherheitsklasse: -; Sonnenschutztyp: Movable; g-Wert: 0,51
 | H2 Ebene +1 | WA-LB | 1155Wa 0000003112 | yes | Codetext | m² | Trockenbauarbeiten | Wand | Außenwand 7-Schalig | WA-LB | 0 | A | 3.75 | 1155HWa0000000985 | NEW | no | yes | 0 | 0.9 | no | 32 | no | Codetext | AllplanAttributes - Sicherheitsklasse: -; Sonnenschutztyp: Movable; g-Wert: 0,51
 | H2 Ebene +1 | WA-HD | 1155Wa 0000003108 | yes | Codetext | m³ | Zimmer- und Holzbauarbeiten | Wand | Außenwand 7-Schalig | WA-HD | 0 | A | 3.75 | 1155HWa0000000985 | NEW | no | yes | 0 | 0.9 | no | 32 | no | Codetext | AllplanAttributes - Sicherheitsklasse: -; Sonnenschutztyp: Movable; g-Wert: 0,51; ash W_laufende Nr. Statik: 2 (W 2.0/ 2.1/ 2.2)
 | H2 Ebene +1 | WA-DL | 1155Wa 0000003104 | yes | Codetext | m³ | Zimmer- und Holzbauarbeiten | Wand | Außenwand 7-Schalig | WA-DL | 0 | A | 3.75 | 1155HWa0000000985 | NEW | no | yes | 0 | 0.9 | no | 32 | no | Codetext | AllplanAttributes - Sicherheitsklasse: -; Sonnenschutztyp: Movable; g-Wert: 0,51
 | H2 Ebene +1 | WA-LB | 1155Wa 0000003100 | yes | Codetext | m² | Trockenbauarbeiten | Wand | Außenwand 7-Schalig | WA-LB | 0 | A | 3.75 | 1155HWa0000000985 | NEW | no | yes | 0 | 0.9 | no | 32 | no | Codetext | AllplanAttributes - Sicherheitsklasse: -; Sonnenschutztyp: Movable; g-Wert: 0,51
 | H2 Ebene +1 | WA-KL | 1155Wa 0000003096 | yes | Codetext | m² | Zimmer- und Holzbauarbeiten | Wand | Außenwand 7-Schalig | WA-KL | 0 | A | 3.75 | 1155HWa0000000985 | NEW | no | yes | 0 | 0.9 | no | 32 | no | Codetext | AllplanAttributes - Sicherheitsklasse: -; Sonnenschutztyp: Movable; g-Wert: 0,51
 | H2 Ebene +1 | WA-TL | 1155Wa 0000003092 | yes | Codetext | m² | Zimmer- und Holzbauarbeiten | Wand | Außenwand 7-Schalig | WA-TL | 0 | A | 3.75 | 1155HWa0000000985 | NEW | no | yes | 0 | 0.9 | no | 32 | no | Codetext | AllplanAttributes - Sicherheitsklasse: -; Sonnenschutztyp: Movable; g-Wert: 0,51
 | H2 Ebene +1 | WA-HS | 1155Wa 0000003088 | yes | Codetext | m² | Zimmer- und Holzbauarbeiten | Wand | Außenwand 7-Schalig | WA-HS | 0 | A | 3.75 | 1155HWa0000000985 | NEW | no | yes | 0 | 0.9 | no | 32 | no | Codetext | AllplanAttributes - Sicherheitsklasse: -; Sonnenschutztyp: Movable; g-Wert: 0,51
2x Gipsfaserplatte | H2 Ebene +1 | WA-LB | 1155Wa 0000003146 | yes |  | m² | Trockenbauarbeiten | Wand | 2x Gipsfaserplatte | WA-LB |  |  | 3.75 | 1155HWa0000000992 | NEW | no | yes | 0 | 0.9 |  | 32 | AllplanAttributes - Sicherheitsklasse: -; Sonnenschutztyp: Movable; g-Wert: 0,51
Holzständer + Zwischendämmung | H2 Ebene +1 | WA-HD | 1155Wa 0000003144 | yes |  | m³ | Zimmer- und Holzbauarbeiten | Wand | Holzständer + Zwischendämmung | WA-HD |  |  | 3.75 | 1155HWa0000000992 | NEW | no | yes | 0 | 0.9 |  | 32 | AllplanAttributes - Sicherheitsklasse: -; Sonnenschutztyp: Movable; g-Wert: 0,51; ash W_laufende Nr. Statik: 2 (W 2.0/ 2.1/ 2.2)
Staffel + Zwischendämmung | H2 Ebene +1 | WA-DL | 1155Wa 0000003142 | yes |  | m³ | Zimmer- und Holzbauarbeiten | Wand | Staffel + Zwischendämmung | WA-DL |  |  | 3.75 | 1155HWa0000000992 | NEW | no | yes | 0 | 0.9 |  | 32 | AllplanAttributes - Sicherheitsklasse: -; Sonnenschutztyp: Movable; g-Wert: 0,51
 | H2 Ebene +1 | WA-LB | 1155Wa 0000003148 | yes | Codetext | m² | Trockenbauarbeiten | Wand | Außenwand 7-Schalig | WA-LB | 0 | A | 3.75 | 1155HWa0000000992 | NEW | no | yes | 0 | 0.9 | no | 32 | no | Codetext | AllplanAttributes - Sicherheitsklasse: -; Sonnenschutztyp: Movable; g-Wert: 0,51
Konterlattung | H2 Ebene +1 | WA-KL | 1155Wa 0000003150 | yes |  | m² | Zimmer- und Holzbauarbeiten | Wand | Konterlattung | WA-KL |  |  | 3.75 | 1155HWa0000000992 | NEW | no | yes | 0 | 0.9 |  | 32 | AllplanAttributes - Sicherheitsklasse: -; Sonnenschutztyp: Movable; g-Wert: 0,51
Traglattung | H2 Ebene +1 | WA-TL | 1155Wa 0000003152 | yes |  | m² | Zimmer- und Holzbauarbeiten | Wand | Traglattung | WA-TL |  |  | 3.75 | 1155HWa0000000992 | NEW | no | yes | 0 | 0.9 |  | 32 | AllplanAttributes - Sicherheitsklasse: -; Sonnenschutztyp: Movable; g-Wert: 0,51
Holzschindel | H2 Ebene +1 | WA-HS | 1155Wa 0000003154 | yes |  | m² | Zimmer- und Holzbauarbeiten | Wand | Holzschindel | WA-HS |  |  | 3.75 | 1155HWa0000000992 | NEW | no | yes | 0 | 0.9 |  | 32 | AllplanAttributes - Sicherheitsklasse: -; Sonnenschutztyp: Movable; g-Wert: 0,51
2x Gipsfaserplatte | H2 Ebene +1 | WA-LB | 1155Wa 0000001169 | yes |  | m² | Trockenbauarbeiten | Wand | 2x Gipsfaserplatte | WA-LB |  |  | 3.75 | 1155HWa0000001001 | NEW | no | yes | 0 | 0.9 |  | 32 | AllplanAttributes - Sicherheitsklasse: -; Sonnenschutztyp: Movable; g-Wert: 0,51
Holzständer + Zwischendämmung | H2 Ebene +1 | WA-HD | 1155Wa 0000001087 | yes |  | m³ | Zimmer- und Holzbauarbeiten | Wand | Holzständer + Zwischendämmung | WA-HD |  |  | 3.75 | 1155HWa0000001001 | NEW | no | yes | 0 | 0.9 |  | 32 | AllplanAttributes - Sicherheitsklasse: -; Sonnenschutztyp: Movable; g-Wert: 0,51; ash W_laufende Nr. Statik: 2 (W 2.0/ 2.1/ 2.2)
Staffel + Zwischendämmung | H2 Ebene +1 | WA-DL | 1155Wa 0000001089 | yes |  | m³ | Zimmer- und Holzbauarbeiten | Wand | Staffel + Zwischendämmung | WA-DL |  |  | 3.75 | 1155HWa0000001001 | NEW | no | yes | 0 | 0.9 |  | 32 | AllplanAttributes - Sicherheitsklasse: -; Sonnenschutztyp: Movable; g-Wert: 0,51
 | H2 Ebene +1 | WA-LB | 1155Wa 0000001167 | yes | Codetext | m² | Trockenbauarbeiten | Wand | Außenwand 7-Schalig | WA-LB | 0 | A | 3.75 | 1155HWa0000001001 | NEW | no | yes | 0 | 0.9 | no | 32 | no | Codetext | AllplanAttributes - Sicherheitsklasse: -; Sonnenschutztyp: Movable; g-Wert: 0,51
Konterlattung | H2 Ebene +1 | WA-KL | 1155Wa 0000001165 | yes |  | m² | Zimmer- und Holzbauarbeiten | Wand | Konterlattung | WA-KL |  |  | 3.75 | 1155HWa0000001001 | NEW | no | yes | 0 | 0.9 |  | 32 | AllplanAttributes - Sicherheitsklasse: -; Sonnenschutztyp: Movable; g-Wert: 0,51
Traglattung | H2 Ebene +1 | WA-TL | 1155Wa 0000001163 | yes |  | m² | Zimmer- und Holzbauarbeiten | Wand | Traglattung | WA-TL |  |  | 3.75 | 1155HWa0000001001 | NEW | no | yes | 0 | 0.9 |  | 32 | AllplanAttributes - Sicherheitsklasse: -; Sonnenschutztyp: Movable; g-Wert: 0,51
Holzschindel | H2 Ebene +1 | WA-HS | 1155Wa 0000001161 | yes |  | m² | Zimmer- und Holzbauarbeiten | Wand | Holzschindel | WA-HS |  |  | 3.75 | 1155HWa0000001001 | NEW | no | yes | 0 | 0.9 |  | 32 | AllplanAttributes - Sicherheitsklasse: -; Sonnenschutztyp: Movable; g-Wert: 0,51
2x Gipsfaserplatte | H2 Ebene +1 | WA-LB | 1155Wa 0000001119 | yes |  | m² | Trockenbauarbeiten | Wand | 2x Gipsfaserplatte | WA-LB |  |  | 3.75 | 1155HWa0000001003 | NEW | no | yes | 0 | 0.9 |  | 32 | AllplanAttributes - Sicherheitsklasse: -; Sonnenschutztyp: Movable; g-Wert: 0,51
Holzständer + Zwischendämmung | H2 Ebene +1 | WA-HD | 1155Wa 0000001121 | yes |  | m³ | Zimmer- und Holzbauarbeiten | Wand | Holzständer + Zwischendämmung | WA-HD |  |  | 3.75 | 1155HWa0000001003 | NEW | no | yes | 0 | 0.9 |  | 32 | AllplanAttributes - Sicherheitsklasse: -; Sonnenschutztyp: Movable; g-Wert: 0,51; ash W_laufende Nr. Statik: 2 (W 2.0/ 2.1/ 2.2)
Staffel + Zwischendämmung | H2 Ebene +1 | WA-DL | 1155Wa 0000001123 | yes |  | m³ | Zimmer- und Holzbauarbeiten | Wand | Staffel + Zwischendämmung | WA-DL |  |  | 3.75 | 1155HWa0000001003 | NEW | no | yes | 0 | 0.9 |  | 32 | AllplanAttributes - Sicherheitsklasse: -; Sonnenschutztyp: Movable; g-Wert: 0,51
 | H2 Ebene +1 | WA-LB | 1155Wa 0000001125 | yes | Codetext | m² | Trockenbauarbeiten | Wand | Außenwand 7-Schalig | WA-LB | 0 | A | 3.75 | 1155HWa0000001003 | NEW | no | yes | 0 | 0.9 | no | 32 | no | Codetext | AllplanAttributes - Sicherheitsklasse: -; Sonnenschutztyp: Movable; g-Wert: 0,51
Konterlattung | H2 Ebene +1 | WA-KL | 1155Wa 0000001127 | yes |  | m² | Zimmer- und Holzbauarbeiten | Wand | Konterlattung | WA-KL |  |  | 3.75 | 1155HWa0000001003 | NEW | no | yes | 0 | 0.9 |  | 32 | AllplanAttributes - Sicherheitsklasse: -; Sonnenschutztyp: Movable; g-Wert: 0,51
Traglattung | H2 Ebene +1 | WA-TL | 1155Wa 0000001129 | yes |  | m² | Zimmer- und Holzbauarbeiten | Wand | Traglattung | WA-TL |  |  | 3.75 | 1155HWa0000001003 | NEW | no | yes | 0 | 0.9 |  | 32 | AllplanAttributes - Sicherheitsklasse: -; Sonnenschutztyp: Movable; g-Wert: 0,51
Holzschindel | H2 Ebene +1 | WA-HS | 1155Wa 0000001131 | yes |  | m² | Zimmer- und Holzbauarbeiten | Wand | Holzschindel | WA-HS |  |  | 3.75 | 1155HWa0000001003 | NEW | no | yes | 0 | 0.9 |  | 32 | AllplanAttributes - Sicherheitsklasse: -; Sonnenschutztyp: Movable; g-Wert: 0,51
 | H2 Ebene +1 | WA-LB | 1155Wa 0000000332 | yes | Codetext | m² | Trockenbauarbeiten | Wand | Außenwand 7-Schalig | WA-LB | 0 | A | 3.75 | 1155HWa0000000194 | NEW | no | yes | 0 | 0.9 | no | 32 | no | Codetext | AllplanAttributes - Sicherheitsklasse: -; Sonnenschutztyp: Movable; g-Wert: 0,51
 | H2 Ebene +1 | WA-HD | 1155Wa 0000000336 | yes | Codetext | m³ | Zimmer- und Holzbauarbeiten | Wand | Außenwand 7-Schalig | WA-HD | 0 | A | 3.75 | 1155HWa0000000194 | NEW | no | yes | 0 | 0.9 | no | 32 | no | Codetext | AllplanAttributes - Sicherheitsklasse: -; Sonnenschutztyp: Movable; g-Wert: 0,51; ash W_laufende Nr. Statik: 2 (W 2.0/ 2.1/ 2.2)
 | H2 Ebene +1 | WA-DL | 1155Wa 0000000356 | yes | Codetext | m³ | Zimmer- und Holzbauarbeiten | Wand | Außenwand 7-Schalig | WA-DL | 0 | A | 3.75 | 1155HWa0000000194 | NEW | no | yes | 0 | 0.9 | no | 32 | no | Codetext | AllplanAttributes - Sicherheitsklasse: -; Sonnenschutztyp: Movable; g-Wert: 0,51
 | H2 Ebene +1 | WA-LB | 1155Wa 0000000352 | yes | Codetext | m² | Trockenbauarbeiten | Wand | Außenwand 7-Schalig | WA-LB | 0 | A | 3.75 | 1155HWa0000000194 | NEW | no | yes | 0 | 0.9 | no | 32 | no | Codetext | AllplanAttributes - Sicherheitsklasse: -; Sonnenschutztyp: Movable; g-Wert: 0,51
 | H2 Ebene +1 | WA-KL | 1155Wa 0000000348 | yes | Codetext | m² | Zimmer- und Holzbauarbeiten | Wand | Außenwand 7-Schalig | WA-KL | 0 | A | 3.75 | 1155HWa0000000194 | NEW | no | yes | 0 | 0.9 | no | 32 | no | Codetext | AllplanAttributes - Sicherheitsklasse: -; Sonnenschutztyp: Movable; g-Wert: 0,51
 | H2 Ebene +1 | WA-TL | 1155Wa 0000000344 | yes | Codetext | m² | Zimmer- und Holzbauarbeiten | Wand | Außenwand 7-Schalig | WA-TL | 0 | A | 3.75 | 1155HWa0000000194 | NEW | no | yes | 0 | 0.9 | no | 32 | no | Codetext | AllplanAttributes - Sicherheitsklasse: -; Sonnenschutztyp: Movable; g-Wert: 0,51
 | H2 Ebene +1 | WA-HS | 1155Wa 0000000340 | yes | Codetext | m² | Zimmer- und Holzbauarbeiten | Wand | Außenwand 7-Schalig | WA-HS | 0 | A | 3.75 | 1155HWa0000000194 | NEW | no | yes | 0 | 0.9 | no | 32 | no | Codetext | AllplanAttributes - Sicherheitsklasse: -; Sonnenschutztyp: Movable; g-Wert: 0,51
2x Gipsfaserplatte | H2 Ebene +1 | WA-LB | 1155Wa 0000001758 | yes |  | m² | Trockenbauarbeiten | Wand | 2x Gipsfaserplatte | WA-LB |  |  | 3.75 | 1155HWa0000000203 | NEW | no | yes | 0 | 0.9 |  | 32 | AllplanAttributes - Sicherheitsklasse: -; Sonnenschutztyp: Movable; g-Wert: 0,51
Holzständer + Zwischendämmung | H2 Ebene +1 | WA-HD | 1155Wa 0000001756 | yes |  | m³ | Zimmer- und Holzbauarbeiten | Wand | Holzständer + Zwischendämmung | WA-HD |  |  | 3.75 | 1155HWa0000000203 | NEW | no | yes | 0 | 0.9 |  | 32 | AllplanAttributes - Sicherheitsklasse: -; Sonnenschutztyp: Movable; g-Wert: 0,51; ash W_laufende Nr. Statik: 2 (W 2.0/ 2.1/ 2.2)
Staffel + Zwischendämmung | H2 Ebene +1 | WA-DL | 1155Wa 0000001754 | yes |  | m³ | Zimmer- und Holzbauarbeiten | Wand | Staffel + Zwischendämmung | WA-DL |  |  | 3.75 | 1155HWa0000000203 | NEW | no | yes | 0 | 0.9 |  | 32 | AllplanAttributes - Sicherheitsklasse: -; Sonnenschutztyp: Movable; g-Wert: 0,51
 | H2 Ebene +1 | WA-LB | 1155Wa 0000001752 | yes | Codetext | m² | Trockenbauarbeiten | Wand | Außenwand 7-Schalig | WA-LB | 0 | A | 3.75 | 1155HWa0000000203 | NEW | no | yes | 0 | 0.9 | no | 32 | no | Codetext | AllplanAttributes - Sicherheitsklasse: -; Sonnenschutztyp: Movable; g-Wert: 0,51
Konterlattung | H2 Ebene +1 | WA-KL | 1155Wa 0000001750 | yes |  | m² | Zimmer- und Holzbauarbeiten | Wand | Konterlattung | WA-KL |  |  | 3.75 | 1155HWa0000000203 | NEW | no | yes | 0 | 0.9 |  | 32 | AllplanAttributes - Sicherheitsklasse: -; Sonnenschutztyp: Movable; g-Wert: 0,51
Traglattung | H2 Ebene +1 | WA-TL | 1155Wa 0000001748 | yes |  | m² | Zimmer- und Holzbauarbeiten | Wand | Traglattung | WA-TL |  |  | 3.75 | 1155HWa0000000203 | NEW | no | yes | 0 | 0.9 |  | 32 | AllplanAttributes - Sicherheitsklasse: -; Sonnenschutztyp: Movable; g-Wert: 0,51
Holzschindel | H2 Ebene +1 | WA-HS | 1155Wa 0000001746 | yes |  | m² | Zimmer- und Holzbauarbeiten | Wand | Holzschindel | WA-HS |  |  | 3.75 | 1155HWa0000000203 | NEW | no | yes | 0 | 0.9 |  | 32 | AllplanAttributes - Sicherheitsklasse: -; Sonnenschutztyp: Movable; g-Wert: 0,51
 | H2 Ebene +1 | WA-LB | 1155Wa 0000000388 | yes | Codetext | m² | Trockenbauarbeiten | Wand | Außenwand 7-Schalig | WA-LB | 0 | A | 3.75 | 1155HWa0000000188 | NEW | no | yes | 0 | 0.9 | no | 32 | no | Codetext | AllplanAttributes - Sicherheitsklasse: -; Sonnenschutztyp: Movable; g-Wert: 0,51
 | H2 Ebene +1 | WA-HD | 1155Wa 0000000384 | yes | Codetext | m³ | Zimmer- und Holzbauarbeiten | Wand | Außenwand 7-Schalig | WA-HD | 0 | A | 3.75 | 1155HWa0000000188 | NEW | no | yes | 0 | 0.9 | no | 32 | no | Codetext | AllplanAttributes - Sicherheitsklasse: -; Sonnenschutztyp: Movable; g-Wert: 0,51; ash W_laufende Nr. Statik: 2 (W 2.0/ 2.1/ 2.2)
 | H2 Ebene +1 | WA-DL | 1155Wa 0000000364 | yes | Codetext | m³ | Zimmer- und Holzbauarbeiten | Wand | Außenwand 7-Schalig | WA-DL | 0 | A | 3.75 | 1155HWa0000000188 | NEW | no | yes | 0 | 0.9 | no | 32 | no | Codetext | AllplanAttributes - Sicherheitsklasse: -; Sonnenschutztyp: Movable; g-Wert: 0,51
 | H2 Ebene +1 | WA-LB | 1155Wa 0000000368 | yes | Codetext | m² | Trockenbauarbeiten | Wand | Außenwand 7-Schalig | WA-LB | 0 | A | 3.75 | 1155HWa0000000188 | NEW | no | yes | 0 | 0.9 | no | 32 | no | Codetext | AllplanAttributes - Sicherheitsklasse: -; Sonnenschutztyp: Movable; g-Wert: 0,51
 | H2 Ebene +1 | WA-KL | 1155Wa 0000000372 | yes | Codetext | m² | Zimmer- und Holzbauarbeiten | Wand | Außenwand 7-Schalig | WA-KL | 0 | A | 3.75 | 1155HWa0000000188 | NEW | no | yes | 0 | 0.9 | no | 32 | no | Codetext | AllplanAttributes - Sicherheitsklasse: -; Sonnenschutztyp: Movable; g-Wert: 0,51
 | H2 Ebene +1 | WA-TL | 1155Wa 0000000376 | yes | Codetext | m² | Zimmer- und Holzbauarbeiten | Wand | Außenwand 7-Schalig | WA-TL | 0 | A | 3.75 | 1155HWa0000000188 | NEW | no | yes | 0 | 0.9 | no | 32 | no | Codetext | AllplanAttributes - Sicherheitsklasse: -; Sonnenschutztyp: Movable; g-Wert: 0,51
 | H2 Ebene +1 | WA-HS | 1155Wa 0000000380 | yes | Codetext | m² | Zimmer- und Holzbauarbeiten | Wand | Außenwand 7-Schalig | WA-HS | 0 | A | 3.75 | 1155HWa0000000188 | NEW | no | yes | 0 | 0.9 | no | 32 | no | Codetext | AllplanAttributes - Sicherheitsklasse: -; Sonnenschutztyp: Movable; g-Wert: 0,51
2x Gipsfaserplatte | H2 Ebene +1 | WA-LB | 1155Wa 0000000398 | yes |  | m² | Trockenbauarbeiten | Wand | 2x Gipsfaserplatte | WA-LB |  |  | 3.75 | 1155HWa0000000201 | NEW | no | yes | 0 | 0.9 |  | 32 | AllplanAttributes - Sicherheitsklasse: -; Sonnenschutztyp: Movable; g-Wert: 0,51
Holzständer + Zwischendämmung | H2 Ebene +1 | WA-HD | 1155Wa 0000000326 | yes |  | m³ | Zimmer- und Holzbauarbeiten | Wand | Holzständer + Zwischendämmung | WA-HD |  |  | 3.75 | 1155HWa0000000201 | NEW | no | yes | 0 | 0.9 |  | 32 | AllplanAttributes - Sicherheitsklasse: -; Sonnenschutztyp: Movable; g-Wert: 0,51; ash W_laufende Nr. Statik: 2 (W 2.0/ 2.1/ 2.2)
Staffel + Zwischendämmung | H2 Ebene +1 | WA-DL | 1155Wa 0000000328 | yes |  | m³ | Zimmer- und Holzbauarbeiten | Wand | Staffel + Zwischendämmung | WA-DL |  |  | 3.75 | 1155HWa0000000201 | NEW | no | yes | 0 | 0.9 |  | 32 | AllplanAttributes - Sicherheitsklasse: -; Sonnenschutztyp: Movable; g-Wert: 0,51
 | H2 Ebene +1 | WA-LB | 1155Wa 0000000396 | yes | Codetext | m² | Trockenbauarbeiten | Wand | Außenwand 7-Schalig | WA-LB | 0 | A | 3.75 | 1155HWa0000000201 | NEW | no | yes | 0 | 0.9 | no | 32 | no | Codetext | AllplanAttributes - Sicherheitsklasse: -; Sonnenschutztyp: Movable; g-Wert: 0,51
Konterlattung | H2 Ebene +1 | WA-KL | 1155Wa 0000000394 | yes |  | m² | Zimmer- und Holzbauarbeiten | Wand | Konterlattung | WA-KL |  |  | 3.75 | 1155HWa0000000201 | NEW | no | yes | 0 | 0.9 |  | 32 | AllplanAttributes - Sicherheitsklasse: -; Sonnenschutztyp: Movable; g-Wert: 0,51
Traglattung | H2 Ebene +1 | WA-TL | 1155Wa 0000000392 | yes |  | m² | Zimmer- und Holzbauarbeiten | Wand | Traglattung | WA-TL |  |  | 3.75 | 1155HWa0000000201 | NEW | no | yes | 0 | 0.9 |  | 32 | AllplanAttributes - Sicherheitsklasse: -; Sonnenschutztyp: Movable; g-Wert: 0,51
Holzschindel | H2 Ebene +1 | WA-HS | 1155Wa 0000000390 | yes |  | m² | Zimmer- und Holzbauarbeiten | Wand | Holzschindel | WA-HS |  |  | 3.75 | 1155HWa0000000201 | NEW | no | yes | 0 | 0.9 |  | 32 | AllplanAttributes - Sicherheitsklasse: -; Sonnenschutztyp: Movable; g-Wert: 0,51
2x Gipsfaserplatte | H2 Ebene +1 | WA-LB | 1155Wa 0000000400 | yes |  | m² | Trockenbauarbeiten | Wand | 2x Gipsfaserplatte | WA-LB |  |  | 3.75 | 1155HWa0000000192 | NEW | no | yes | 0 | 0.9 |  | 32 | AllplanAttributes - Sicherheitsklasse: -; Sonnenschutztyp: Movable; g-Wert: 0,51
Holzständer + Zwischendämmung | H2 Ebene +1 | WA-HD | 1155Wa 0000000360 | yes |  | m³ | Zimmer- und Holzbauarbeiten | Wand | Holzständer + Zwischendämmung | WA-HD |  |  | 3.75 | 1155HWa0000000192 | NEW | no | yes | 0 | 0.9 |  | 32 | AllplanAttributes - Sicherheitsklasse: -; Sonnenschutztyp: Movable; g-Wert: 0,51; ash W_laufende Nr. Statik: 2 (W 2.0/ 2.1/ 2.2)
Staffel + Zwischendämmung | H2 Ebene +1 | WA-DL | 1155Wa 0000000358 | yes |  | m³ | Zimmer- und Holzbauarbeiten | Wand | Staffel + Zwischendämmung | WA-DL |  |  | 3.75 | 1155HWa0000000192 | NEW | no | yes | 0 | 0.9 |  | 32 | AllplanAttributes - Sicherheitsklasse: -; Sonnenschutztyp: Movable; g-Wert: 0,51
 | H2 Ebene +1 | WA-LB | 1155Wa 0000000430 | yes | Codetext | m² | Trockenbauarbeiten | Wand | Außenwand 7-Schalig | WA-LB | 0 | A | 3.75 | 1155HWa0000000192 | NEW | no | yes | 0 | 0.9 | no | 32 | no | Codetext | AllplanAttributes - Sicherheitsklasse: -; Sonnenschutztyp: Movable; g-Wert: 0,51
Konterlattung | H2 Ebene +1 | WA-KL | 1155Wa 0000000432 | yes |  | m² | Zimmer- und Holzbauarbeiten | Wand | Konterlattung | WA-KL |  |  | 3.75 | 1155HWa0000000192 | NEW | no | yes | 0 | 0.9 |  | 32 | AllplanAttributes - Sicherheitsklasse: -; Sonnenschutztyp: Movable; g-Wert: 0,51
Traglattung | H2 Ebene +1 | WA-TL | 1155Wa 0000000434 | yes |  | m² | Zimmer- und Holzbauarbeiten | Wand | Traglattung | WA-TL |  |  | 3.75 | 1155HWa0000000192 | NEW | no | yes | 0 | 0.9 |  | 32 | AllplanAttributes - Sicherheitsklasse: -; Sonnenschutztyp: Movable; g-Wert: 0,51
Holzschindel | H2 Ebene +1 | WA-HS | 1155Wa 0000000436 | yes |  | m² | Zimmer- und Holzbauarbeiten | Wand | Holzschindel | WA-HS |  |  | 3.75 | 1155HWa0000000192 | NEW | no | yes | 0 | 0.9 |  | 32 | AllplanAttributes - Sicherheitsklasse: -; Sonnenschutztyp: Movable; g-Wert: 0,51
 | H2 Ebene +1 | WA-LB | 1155Wa 0000000706 | yes | Codetext | m² | Trockenbauarbeiten | Wand | Außenwand 7-Schalig | WA-LB | 0 | A | 3.75 | 1155HWa0000000545 | NEW | no | yes | 0 | 0.9 | no | 35 | no | Codetext | AllplanAttributes - Sicherheitsklasse: -; Sonnenschutztyp: Movable; g-Wert: 0,51
 | H2 Ebene +1 | WA-HD | 1155Wa 0000000710 | yes | Codetext | m³ | Zimmer- und Holzbauarbeiten | Wand | Außenwand 7-Schalig | WA-HD | 0 | A | 3.75 | 1155HWa0000000545 | NEW | no | yes | 0 | 0.9 | no | 35 | no | Codetext | AllplanAttributes - Sicherheitsklasse: -; Sonnenschutztyp: Movable; g-Wert: 0,51; ash W_laufende Nr. Statik: 2 (W 2.0/ 2.1/ 2.2)
 | H2 Ebene +1 | WA-DL | 1155Wa 0000000730 | yes | Codetext | m³ | Zimmer- und Holzbauarbeiten | Wand | Außenwand 7-Schalig | WA-DL | 0 | A | 3.75 | 1155HWa0000000545 | NEW | no | yes | 0 | 0.9 | no | 35 | no | Codetext | AllplanAttributes - Sicherheitsklasse: -; Sonnenschutztyp: Movable; g-Wert: 0,51
 | H2 Ebene +1 | WA-LB | 1155Wa 0000000726 | yes | Codetext | m² | Trockenbauarbeiten | Wand | Außenwand 7-Schalig | WA-LB | 0 | A | 3.75 | 1155HWa0000000545 | NEW | no | yes | 0 | 0.9 | no | 35 | no | Codetext | AllplanAttributes - Sicherheitsklasse: -; Sonnenschutztyp: Movable; g-Wert: 0,51
 | H2 Ebene +1 | WA-KL | 1155Wa 0000000722 | yes | Codetext | m² | Zimmer- und Holzbauarbeiten | Wand | Außenwand 7-Schalig | WA-KL | 0 | A | 3.75 | 1155HWa0000000545 | NEW | no | yes | 0 | 0.9 | no | 35 | no | Codetext | AllplanAttributes - Sicherheitsklasse: -; Sonnenschutztyp: Movable; g-Wert: 0,51
 | H2 Ebene +1 | WA-TL | 1155Wa 0000000718 | yes | Codetext | m² | Zimmer- und Holzbauarbeiten | Wand | Außenwand 7-Schalig | WA-TL | 0 | A | 3.75 | 1155HWa0000000545 | NEW | no | yes | 0 | 0.9 | no | 35 | no | Codetext | AllplanAttributes - Sicherheitsklasse: -; Sonnenschutztyp: Movable; g-Wert: 0,51
 | H2 Ebene +1 | WA-HS | 1155Wa 0000000714 | yes | Codetext | m² | Zimmer- und Holzbauarbeiten | Wand | Außenwand 7-Schalig | WA-HS | 0 | A | 3.75 | 1155HWa0000000545 | NEW | no | yes | 0 | 0.9 | no | 35 | no | Codetext | AllplanAttributes - Sicherheitsklasse: -; Sonnenschutztyp: Movable; g-Wert: 0,51
2x Gipsfaserplatte | H2 Ebene +1 | WA-LB | 1155Wa 0000000692 | yes |  | m² | Trockenbauarbeiten | Wand | 2x Gipsfaserplatte | WA-LB |  |  | 3.75 | 1155HWa0000000549 | NEW | no | yes | 0 | 0.9 |  | 35 | AllplanAttributes - Sicherheitsklasse: -; Sonnenschutztyp: Movable; g-Wert: 0,51
Holzständer + Zwischendämmung | H2 Ebene +1 | WA-HD | 1155Wa 0000000732 | yes |  | m³ | Zimmer- und Holzbauarbeiten | Wand | Holzständer + Zwischendämmung | WA-HD |  |  | 3.75 | 1155HWa0000000549 | NEW | no | yes | 0 | 0.9 |  | 35 | AllplanAttributes - Sicherheitsklasse: -; Sonnenschutztyp: Movable; g-Wert: 0,51; ash W_laufende Nr. Statik: 2 (W 2.0/ 2.1/ 2.2)
Staffel + Zwischendämmung | H2 Ebene +1 | WA-DL | 1155Wa 0000000734 | yes |  | m³ | Zimmer- und Holzbauarbeiten | Wand | Staffel + Zwischendämmung | WA-DL |  |  | 3.75 | 1155HWa0000000549 | NEW | no | yes | 0 | 0.9 |  | 35 | AllplanAttributes - Sicherheitsklasse: -; Sonnenschutztyp: Movable; g-Wert: 0,51
 | H2 Ebene +1 | WA-LB | 1155Wa 0000000686 | yes | Codetext | m² | Trockenbauarbeiten | Wand | Außenwand 7-Schalig | WA-LB | 0 | A | 3.75 | 1155HWa0000000549 | NEW | no | yes | 0 | 0.9 | no | 35 | no | Codetext | AllplanAttributes - Sicherheitsklasse: -; Sonnenschutztyp: Movable; g-Wert: 0,51
Konterlattung | H2 Ebene +1 | WA-KL | 1155Wa 0000000684 | yes |  | m² | Zimmer- und Holzbauarbeiten | Wand | Konterlattung | WA-KL |  |  | 3.75 | 1155HWa0000000549 | NEW | no | yes | 0 | 0.9 |  | 35 | AllplanAttributes - Sicherheitsklasse: -; Sonnenschutztyp: Movable; g-Wert: 0,51
Traglattung | H2 Ebene +1 | WA-TL | 1155Wa 0000000682 | yes |  | m² | Zimmer- und Holzbauarbeiten | Wand | Traglattung | WA-TL |  |  | 3.75 | 1155HWa0000000549 | NEW | no | yes | 0 | 0.9 |  | 35 | AllplanAttributes - Sicherheitsklasse: -; Sonnenschutztyp: Movable; g-Wert: 0,51
Holzschindel | H2 Ebene +1 | WA-HS | 1155Wa 0000000680 | yes |  | m² | Zimmer- und Holzbauarbeiten | Wand | Holzschindel | WA-HS |  |  | 3.75 | 1155HWa0000000549 | NEW | no | yes | 0 | 0.9 |  | 35 | AllplanAttributes - Sicherheitsklasse: -; Sonnenschutztyp: Movable; g-Wert: 0,51
 | H2 Ebene +1 | WA-LB | 1155Wa 0000000762 | yes | Codetext | m² | Trockenbauarbeiten | Wand | Außenwand 7-Schalig | WA-LB | 0 | A | 3.75 | 1155HWa0000000551 | NEW | no | yes | 0 | 0.9 | no | 35 | no | Codetext | AllplanAttributes - Sicherheitsklasse: -; Sonnenschutztyp: Movable; g-Wert: 0,51
 | H2 Ebene +1 | WA-HD | 1155Wa 0000000758 | yes | Codetext | m³ | Zimmer- und Holzbauarbeiten | Wand | Außenwand 7-Schalig | WA-HD | 0 | A | 3.75 | 1155HWa0000000551 | NEW | no | yes | 0 | 0.9 | no | 35 | no | Codetext | AllplanAttributes - Sicherheitsklasse: -; Sonnenschutztyp: Movable; g-Wert: 0,51; ash W_laufende Nr. Statik: 2 (W 2.0/ 2.1/ 2.2)
 | H2 Ebene +1 | WA-DL | 1155Wa 0000000738 | yes | Codetext | m³ | Zimmer- und Holzbauarbeiten | Wand | Außenwand 7-Schalig | WA-DL | 0 | A | 3.75 | 1155HWa0000000551 | NEW | no | yes | 0 | 0.9 | no | 35 | no | Codetext | AllplanAttributes - Sicherheitsklasse: -; Sonnenschutztyp: Movable; g-Wert: 0,51
 | H2 Ebene +1 | WA-LB | 1155Wa 0000000742 | yes | Codetext | m² | Trockenbauarbeiten | Wand | Außenwand 7-Schalig | WA-LB | 0 | A | 3.75 | 1155HWa0000000551 | NEW | no | yes | 0 | 0.9 | no | 35 | no | Codetext | AllplanAttributes - Sicherheitsklasse: -; Sonnenschutztyp: Movable; g-Wert: 0,51
 | H2 Ebene +1 | WA-KL | 1155Wa 0000000746 | yes | Codetext | m² | Zimmer- und Holzbauarbeiten | Wand | Außenwand 7-Schalig | WA-KL | 0 | A | 3.75 | 1155HWa0000000551 | NEW | no | yes | 0 | 0.9 | no | 35 | no | Codetext | AllplanAttributes - Sicherheitsklasse: -; Sonnenschutztyp: Movable; g-Wert: 0,51
 | H2 Ebene +1 | WA-TL | 1155Wa 0000000750 | yes | Codetext | m² | Zimmer- und Holzbauarbeiten | Wand | Außenwand 7-Schalig | WA-TL | 0 | A | 3.75 | 1155HWa0000000551 | NEW | no | yes | 0 | 0.9 | no | 35 | no | Codetext | AllplanAttributes - Sicherheitsklasse: -; Sonnenschutztyp: Movable; g-Wert: 0,51
 | H2 Ebene +1 | WA-HS | 1155Wa 0000000754 | yes | Codetext | m² | Zimmer- und Holzbauarbeiten | Wand | Außenwand 7-Schalig | WA-HS | 0 | A | 3.75 | 1155HWa0000000551 | NEW | no | yes | 0 | 0.9 | no | 35 | no | Codetext | AllplanAttributes - Sicherheitsklasse: -; Sonnenschutztyp: Movable; g-Wert: 0,51
2x Gipsfaserplatte | H2 Ebene +1 | WA-LB | 1155Wa 0000000694 | yes |  | m² | Trockenbauarbeiten | Wand | 2x Gipsfaserplatte | WA-LB |  |  | 3.75 | 1155HWa0000000558 | NEW | no | yes | 0 | 0.9 |  | 35 | AllplanAttributes - Sicherheitsklasse: -; Sonnenschutztyp: Movable; g-Wert: 0,51
Holzständer + Zwischendämmung | H2 Ebene +1 | WA-HD | 1155Wa 0000000766 | yes |  | m³ | Zimmer- und Holzbauarbeiten | Wand | Holzständer + Zwischendämmung | WA-HD |  |  | 3.75 | 1155HWa0000000558 | NEW | no | yes | 0 | 0.9 |  | 35 | AllplanAttributes - Sicherheitsklasse: -; Sonnenschutztyp: Movable; g-Wert: 0,51; ash W_laufende Nr. Statik: 2 (W 2.0/ 2.1/ 2.2)
Staffel + Zwischendämmung | H2 Ebene +1 | WA-DL | 1155Wa 0000000764 | yes |  | m³ | Zimmer- und Holzbauarbeiten | Wand | Staffel + Zwischendämmung | WA-DL |  |  | 3.75 | 1155HWa0000000558 | NEW | no | yes | 0 | 0.9 |  | 35 | AllplanAttributes - Sicherheitsklasse: -; Sonnenschutztyp: Movable; g-Wert: 0,51
 | H2 Ebene +1 | WA-LB | 1155Wa 0000000696 | yes | Codetext | m² | Trockenbauarbeiten | Wand | Außenwand 7-Schalig | WA-LB | 0 | A | 3.75 | 1155HWa0000000558 | NEW | no | yes | 0 | 0.9 | no | 35 | no | Codetext | AllplanAttributes - Sicherheitsklasse: -; Sonnenschutztyp: Movable; g-Wert: 0,51
Konterlattung | H2 Ebene +1 | WA-KL | 1155Wa 0000000698 | yes |  | m² | Zimmer- und Holzbauarbeiten | Wand | Konterlattung | WA-KL |  |  | 3.75 | 1155HWa0000000558 | NEW | no | yes | 0 | 0.9 |  | 35 | AllplanAttributes - Sicherheitsklasse: -; Sonnenschutztyp: Movable; g-Wert: 0,51
Traglattung | H2 Ebene +1 | WA-TL | 1155Wa 0000000700 | yes |  | m² | Zimmer- und Holzbauarbeiten | Wand | Traglattung | WA-TL |  |  | 3.75 | 1155HWa0000000558 | NEW | no | yes | 0 | 0.9 |  | 35 | AllplanAttributes - Sicherheitsklasse: -; Sonnenschutztyp: Movable; g-Wert: 0,51
Holzschindel | H2 Ebene +1 | WA-HS | 1155Wa 0000000702 | yes |  | m² | Zimmer- und Holzbauarbeiten | Wand | Holzschindel | WA-HS |  |  | 3.75 | 1155HWa0000000558 | NEW | no | yes | 0 | 0.9 |  | 35 | AllplanAttributes - Sicherheitsklasse: -; Sonnenschutztyp: Movable; g-Wert: 0,51
 | H2 Ebene +1 | WA-LB | 1155Wa 0000002063 | yes | Codetext | m² | Trockenbauarbeiten | Wand | Außenwand 7-Schalig | WA-LB | 0 | A | 3.75 | 1155HWa0000000555 | NEW | no | yes | 0 | 0.9 | no | 35 | no | Codetext | AllplanAttributes - Sicherheitsklasse: -; Sonnenschutztyp: Movable; g-Wert: 0,51
 | H2 Ebene +1 | WA-HD | 1155Wa 0000002059 | yes | Codetext | m³ | Zimmer- und Holzbauarbeiten | Wand | Außenwand 7-Schalig | WA-HD | 0 | A | 3.75 | 1155HWa0000000555 | NEW | no | yes | 0 | 0.9 | no | 35 | no | Codetext | AllplanAttributes - ash D_Detailverweis: DT C; ash D_Plannummer: D1851; Sicherheitsklasse: -; Sonnenschutztyp: Movable; g-Wert: 0,51; ash W_laufende Nr. Statik: 2 (W 2.0/ 2.1/ 2.2)
 | H2 Ebene +1 | WA-DL | 1155Wa 0000002055 | yes | Codetext | m³ | Zimmer- und Holzbauarbeiten | Wand | Außenwand 7-Schalig | WA-DL | 0 | A | 3.75 | 1155HWa0000000555 | NEW | no | yes | 0 | 0.9 | no | 35 | no | Codetext | AllplanAttributes - Sicherheitsklasse: -; Sonnenschutztyp: Movable; g-Wert: 0,51
 | H2 Ebene +1 | WA-LB | 1155Wa 0000002051 | yes | Codetext | m² | Trockenbauarbeiten | Wand | Außenwand 7-Schalig | WA-LB | 0 | A | 3.75 | 1155HWa0000000555 | NEW | no | yes | 0 | 0.9 | no | 35 | no | Codetext | AllplanAttributes - Sicherheitsklasse: -; Sonnenschutztyp: Movable; g-Wert: 0,51
 | H2 Ebene +1 | WA-KL | 1155Wa 0000002047 | yes | Codetext | m² | Zimmer- und Holzbauarbeiten | Wand | Außenwand 7-Schalig | WA-KL | 0 | A | 3.75 | 1155HWa0000000555 | NEW | no | yes | 0 | 0.9 | no | 35 | no | Codetext | AllplanAttributes - Sicherheitsklasse: -; Sonnenschutztyp: Movable; g-Wert: 0,51
 | H2 Ebene +1 | WA-TL | 1155Wa 0000002043 | yes | Codetext | m² | Zimmer- und Holzbauarbeiten | Wand | Außenwand 7-Schalig | WA-TL | 0 | A | 3.75 | 1155HWa0000000555 | NEW | no | yes | 0 | 0.9 | no | 35 | no | Codetext | AllplanAttributes - Sicherheitsklasse: -; Sonnenschutztyp: Movable; g-Wert: 0,51
 | H2 Ebene +1 | WA-HS | 1155Wa 0000002039 | yes | Codetext | m² | Zimmer- und Holzbauarbeiten | Wand | Außenwand 7-Schalig | WA-HS | 0 | A | 3.75 | 1155HWa0000000555 | NEW | no | yes | 0 | 0.9 | no | 35 | no | Codetext | AllplanAttributes - Sicherheitsklasse: -; Sonnenschutztyp: Movable; g-Wert: 0,51
2x Gipsfaserplatte | H2 Ebene +1 | WA-LB | 1155Wa 0000001941 | yes |  | m² | Trockenbauarbeiten | Wand | 2x Gipsfaserplatte | WA-LB |  |  | 3.75 | 1155HWa0000000560 | NEW | no | yes | 0 | 0.9 |  | 35 | AllplanAttributes - Sicherheitsklasse: -; Sonnenschutztyp: Movable; g-Wert: 0,51
Holzständer + Zwischendämmung | H2 Ebene +1 | WA-HD | 1155Wa 0000001943 | yes |  | m³ | Zimmer- und Holzbauarbeiten | Wand | Holzständer + Zwischendämmung | WA-HD |  |  | 3.75 | 1155HWa0000000560 | NEW | no | yes | 0 | 0.9 |  | 35 | AllplanAttributes - Sicherheitsklasse: -; Sonnenschutztyp: Movable; g-Wert: 0,51; ash W_laufende Nr. Statik: 2 (W 2.0/ 2.1/ 2.2)
Staffel + Zwischendämmung | H2 Ebene +1 | WA-DL | 1155Wa 0000001945 | yes |  | m³ | Zimmer- und Holzbauarbeiten | Wand | Staffel + Zwischendämmung | WA-DL |  |  | 3.75 | 1155HWa0000000560 | NEW | no | yes | 0 | 0.9 |  | 35 | AllplanAttributes - Sicherheitsklasse: -; Sonnenschutztyp: Movable; g-Wert: 0,51
 | H2 Ebene +1 | WA-LB | 1155Wa 0000001947 | yes | Codetext | m² | Trockenbauarbeiten | Wand | Außenwand 7-Schalig | WA-LB | 0 | A | 3.75 | 1155HWa0000000560 | NEW | no | yes | 0 | 0.9 | no | 35 | no | Codetext | AllplanAttributes - Sicherheitsklasse: -; Sonnenschutztyp: Movable; g-Wert: 0,51
Konterlattung | H2 Ebene +1 | WA-KL | 1155Wa 0000001949 | yes |  | m² | Zimmer- und Holzbauarbeiten | Wand | Konterlattung | WA-KL |  |  | 3.75 | 1155HWa0000000560 | NEW | no | yes | 0 | 0.9 |  | 35 | AllplanAttributes - Sicherheitsklasse: -; Sonnenschutztyp: Movable; g-Wert: 0,51
Traglattung | H2 Ebene +1 | WA-TL | 1155Wa 0000001951 | yes |  | m² | Zimmer- und Holzbauarbeiten | Wand | Traglattung | WA-TL |  |  | 3.75 | 1155HWa0000000560 | NEW | no | yes | 0 | 0.9 |  | 35 | AllplanAttributes - Sicherheitsklasse: -; Sonnenschutztyp: Movable; g-Wert: 0,51
Holzschindel | H2 Ebene +1 | WA-HS | 1155Wa 0000001953 | yes |  | m² | Zimmer- und Holzbauarbeiten | Wand | Holzschindel | WA-HS |  |  | 3.75 | 1155HWa0000000560 | NEW | no | yes | 0 | 0.9 |  | 35 | AllplanAttributes - Sicherheitsklasse: -; Sonnenschutztyp: Movable; g-Wert: 0,51
2x Gipsfaserplatte | H2 Ebene +1 | WA-LB | 1155Wa 0000002623 | yes |  | m² | Trockenbauarbeiten | Wand | 2x Gipsfaserplatte | WA-LB |  |  | 3.75 | 1155HWa0000002407 | NEW | no | yes | 0 | 0.9 |  | 32 | AllplanAttributes - Sicherheitsklasse: -; Sonnenschutztyp: Movable; g-Wert: 0,51
Holzständer + Zwischendämmung | H2 Ebene +1 | WA-HD | 1155Wa 0000002619 | yes |  | m³ | Zimmer- und Holzbauarbeiten | Wand | Holzständer + Zwischendämmung | WA-HD |  |  | 3.75 | 1155HWa0000002407 | NEW | no | yes | 0 | 0.9 |  | 32 | AllplanAttributes - ash D_Detailverweis: DT D; ash D_Plannummer: D1851; Sicherheitsklasse: -; Sonnenschutztyp: Movable; g-Wert: 0,51; ash W_laufende Nr. Statik: 5 (W 4.0)
Staffel + Zwischendämmung | H2 Ebene +1 | WA-DL | 1155Wa 0000002614 | yes |  | m³ | Zimmer- und Holzbauarbeiten | Wand | Staffel + Zwischendämmung | WA-DL |  |  | 3.75 | 1155HWa0000002407 | NEW | no | yes | 0 | 0.9 |  | 32 | AllplanAttributes - Sicherheitsklasse: -; Sonnenschutztyp: Movable; g-Wert: 0,51
 | H2 Ebene +1 | WA-LB | 1155Wa 0000002609 | yes | Codetext | m² | Trockenbauarbeiten | Wand | Außenwand 7-Schalig | WA-LB | 0 | A | 3.75 | 1155HWa0000002407 | NEW | no | yes | 0 | 0.9 | no | 32 | no | Codetext | AllplanAttributes - Sicherheitsklasse: -; Sonnenschutztyp: Movable; g-Wert: 0,51
Konterlattung | H2 Ebene +1 | WA-KL | 1155Wa 0000002605 | yes |  | m² | Zimmer- und Holzbauarbeiten | Wand | Konterlattung | WA-KL |  |  | 3.75 | 1155HWa0000002407 | NEW | no | yes | 0 | 0.9 |  | 32 | AllplanAttributes - Sicherheitsklasse: -; Sonnenschutztyp: Movable; g-Wert: 0,51
Traglattung | H2 Ebene +1 | WA-TL | 1155Wa 0000002601 | yes |  | m² | Zimmer- und Holzbauarbeiten | Wand | Traglattung | WA-TL |  |  | 3.75 | 1155HWa0000002407 | NEW | no | yes | 0 | 0.9 |  | 32 | AllplanAttributes - Sicherheitsklasse: -; Sonnenschutztyp: Movable; g-Wert: 0,51
Keramikschindel | H2 Ebene +1 | WA-HS | 1155Wa 0000002680 | yes |  | m² | Zimmer- und Holzbauarbeiten | Wand | Keramikschindel | WA-HS |  |  | 3.75 | 1155HWa0000002407 | NEW | no | yes | 0 | 0.9 |  | 32 | AllplanAttributes - Sicherheitsklasse: -; Sonnenschutztyp: Movable; g-Wert: 0,51
2x Gipsfaserplatte | H2 Ebene +1 | WA-LB | 1155Wa 0000002682 | yes |  | m² | Trockenbauarbeiten | Wand | 2x Gipsfaserplatte | WA-LB |  |  | 3.75 | 1155HWa0000002532 | NEW | no | yes | 0 | 0.9 |  | 32 | AllplanAttributes - Sicherheitsklasse: -; Sonnenschutztyp: Movable; g-Wert: 0,51
Holzständer + Zwischendämmung | H2 Ebene +1 | WA-HD | 1155Wa 0000002684 | yes |  | m³ | Zimmer- und Holzbauarbeiten | Wand | Holzständer + Zwischendämmung | WA-HD |  |  | 3.75 | 1155HWa0000002532 | NEW | no | yes | 0 | 0.9 |  | 32 | AllplanAttributes - Sicherheitsklasse: -; Sonnenschutztyp: Movable; g-Wert: 0,51; ash W_laufende Nr. Statik: 5 (W 4.0)
Staffel + Zwischendämmung | H2 Ebene +1 | WA-DL | 1155Wa 0000002686 | yes |  | m³ | Zimmer- und Holzbauarbeiten | Wand | Staffel + Zwischendämmung | WA-DL |  |  | 3.75 | 1155HWa0000002532 | NEW | no | yes | 0 | 0.9 |  | 32 | AllplanAttributes - Sicherheitsklasse: -; Sonnenschutztyp: Movable; g-Wert: 0,51
 | H2 Ebene +1 | WA-LB | 1155Wa 0000002688 | yes | Codetext | m² | Trockenbauarbeiten | Wand | Außenwand 7-Schalig | WA-LB | 0 | A | 3.75 | 1155HWa0000002532 | NEW | no | yes | 0 | 0.9 | no | 32 | no | Codetext | AllplanAttributes - Sicherheitsklasse: -; Sonnenschutztyp: Movable; g-Wert: 0,51
Konterlattung | H2 Ebene +1 | WA-KL | 1155Wa 0000002690 | yes |  | m² | Zimmer- und Holzbauarbeiten | Wand | Konterlattung | WA-KL |  |  | 3.75 | 1155HWa0000002532 | NEW | no | yes | 0 | 0.9 |  | 32 | AllplanAttributes - Sicherheitsklasse: -; Sonnenschutztyp: Movable; g-Wert: 0,51
Traglattung | H2 Ebene +1 | WA-TL | 1155Wa 0000002692 | yes |  | m² | Zimmer- und Holzbauarbeiten | Wand | Traglattung | WA-TL |  |  | 3.75 | 1155HWa0000002532 | NEW | no | yes | 0 | 0.9 |  | 32 | AllplanAttributes - Sicherheitsklasse: -; Sonnenschutztyp: Movable; g-Wert: 0,51
2x Gipsfaserplatte | H2 Ebene +1 | WA-LB | 1155Wa 0000002558 | yes |  | m² | Trockenbauarbeiten | Wand | 2x Gipsfaserplatte | WA-LB |  |  | 3.75 | 1155HWa0000002531 | NEW | no | yes | 0 | 0.9 |  | 32 | AllplanAttributes - Sicherheitsklasse: -; Sonnenschutztyp: Movable; g-Wert: 0,51
Holzständer + Zwischendämmung | H2 Ebene +1 | WA-HD | 1155Wa 0000002560 | yes |  | m³ | Zimmer- und Holzbauarbeiten | Wand | Holzständer + Zwischendämmung | WA-HD |  |  | 3.75 | 1155HWa0000002531 | NEW | no | yes | 0 | 0.9 |  | 32 | AllplanAttributes - Sicherheitsklasse: -; Sonnenschutztyp: Movable; g-Wert: 0,51; ash W_laufende Nr. Statik: 5 (W 4.0)
Staffel + Zwischendämmung | H2 Ebene +1 | WA-DL | 1155Wa 0000002562 | yes |  | m³ | Zimmer- und Holzbauarbeiten | Wand | Staffel + Zwischendämmung | WA-DL |  |  | 3.75 | 1155HWa0000002531 | NEW | no | yes | 0 | 0.9 |  | 32 | AllplanAttributes - Sicherheitsklasse: -; Sonnenschutztyp: Movable; g-Wert: 0,51
 | H2 Ebene +1 | WA-LB | 1155Wa 0000002564 | yes | Codetext | m² | Trockenbauarbeiten | Wand | Außenwand 7-Schalig | WA-LB | 0 | A | 3.75 | 1155HWa0000002531 | NEW | no | yes | 0 | 0.9 | no | 32 | no | Codetext | AllplanAttributes - Sicherheitsklasse: -; Sonnenschutztyp: Movable; g-Wert: 0,51
Konterlattung | H2 Ebene +1 | WA-KL | 1155Wa 0000002566 | yes |  | m² | Zimmer- und Holzbauarbeiten | Wand | Konterlattung | WA-KL |  |  | 3.75 | 1155HWa0000002531 | NEW | no | yes | 0 | 0.9 |  | 32 | AllplanAttributes - Sicherheitsklasse: -; Sonnenschutztyp: Movable; g-Wert: 0,51
Traglattung | H2 Ebene +1 | WA-TL | 1155Wa 0000002568 | yes |  | m² | Zimmer- und Holzbauarbeiten | Wand | Traglattung | WA-TL |  |  | 3.75 | 1155HWa0000002531 | NEW | no | yes | 0 | 0.9 |  | 32 | AllplanAttributes - Sicherheitsklasse: -; Sonnenschutztyp: Movable; g-Wert: 0,51
 | H2 Ebene +1 | WA-LB | 1155Wa 0000002556 | yes | Codetext | m² | Trockenbauarbeiten | Wand | Außenwand 7-Schalig | WA-LB | 0 | A | 3.75 | 1155HWa0000002503 | NEW | no | yes | 0 | 0.9 | no | 32 | no | Codetext | AllplanAttributes - Sicherheitsklasse: -; Sonnenschutztyp: Movable; g-Wert: 0,51
 | H2 Ebene +1 | WA-HD | 1155Wa 0000002554 | yes | Codetext | m³ | Zimmer- und Holzbauarbeiten | Wand | Außenwand 7-Schalig | WA-HD | 0 | A | 3.75 | 1155HWa0000002503 | NEW | no | yes | 0 | 0.9 | no | 32 | no | Codetext | AllplanAttributes - Sicherheitsklasse: -; Sonnenschutztyp: Movable; g-Wert: 0,51; ash W_laufende Nr. Statik: 5 (W 4.0)
 | H2 Ebene +1 | WA-DL | 1155Wa 0000002552 | yes | Codetext | m³ | Zimmer- und Holzbauarbeiten | Wand | Außenwand 7-Schalig | WA-DL | 0 | A | 3.75 | 1155HWa0000002503 | NEW | no | yes | 0 | 0.9 | no | 32 | no | Codetext | AllplanAttributes - Sicherheitsklasse: -; Sonnenschutztyp: Movable; g-Wert: 0,51
 | H2 Ebene +1 | WA-LB | 1155Wa 0000002550 | yes | Codetext | m² | Trockenbauarbeiten | Wand | Außenwand 7-Schalig | WA-LB | 0 | A | 3.75 | 1155HWa0000002503 | NEW | no | yes | 0 | 0.9 | no | 32 | no | Codetext | AllplanAttributes - Sicherheitsklasse: -; Sonnenschutztyp: Movable; g-Wert: 0,51
 | H2 Ebene +1 | WA-KL | 1155Wa 0000002548 | yes | Codetext | m² | Zimmer- und Holzbauarbeiten | Wand | Außenwand 7-Schalig | WA-KL | 0 | A | 3.75 | 1155HWa0000002503 | NEW | no | yes | 0 | 0.9 | no | 32 | no | Codetext | AllplanAttributes - Sicherheitsklasse: -; Sonnenschutztyp: Movable; g-Wert: 0,51
 | H2 Ebene +1 | WA-TL | 1155Wa 0000002546 | yes | Codetext | m² | Zimmer- und Holzbauarbeiten | Wand | Außenwand 7-Schalig | WA-TL | 0 | A | 3.75 | 1155HWa0000002503 | NEW | no | yes | 0 | 0.9 | no | 32 | no | Codetext | AllplanAttributes - Sicherheitsklasse: -; Sonnenschutztyp: Movable; g-Wert: 0,51
Keramikschindel | H2 Ebene +1 | WA-HS | 1155Wa 0000002544 | yes | Codetext | m² | Zimmer- und Holzbauarbeiten | Wand | Keramikschindel | WA-HS | 0 | A | 3.75 | 1155HWa0000002503 | NEW | no | yes | 0 | 0.9 | no | 32 | no | Codetext | AllplanAttributes - Sicherheitsklasse: -; Sonnenschutztyp: Movable; g-Wert: 0,51
2x Gipsfaserplatte | H2 Ebene +1 | WA-LB | 1155Wa 0000002517 | yes |  | m² | Trockenbauarbeiten | Wand | 2x Gipsfaserplatte | WA-LB |  |  | 3.75 | 1155HWa0000000826 | NEW | no | yes | 0 | 0.9 |  | 32 | AllplanAttributes - Sicherheitsklasse: -; Sonnenschutztyp: Movable; g-Wert: 0,51
Holzständer + Zwischendämmung | H2 Ebene +1 | WA-DL | 1155Wa 0000002519 | yes |  | m³ | Zimmer- und Holzbauarbeiten | Wand | Holzständer + Zwischendämmung | WA-DL |  |  | 3.75 | 1155HWa0000000826 | NEW | no | yes | 0 | 0.9 |  | 32 | AllplanAttributes - Sicherheitsklasse: -; Sonnenschutztyp: Movable; g-Wert: 0,51; ash W_laufende Nr. Statik: 2 (W 2.0/ 2.1/ 2.2)
Staffel + Zwischendämmung | H2 Ebene +1 | WA-DL | 1155Wa 0000002521 | yes |  | m³ | Zimmer- und Holzbauarbeiten | Wand | Staffel + Zwischendämmung | WA-DL |  |  | 3.75 | 1155HWa0000000826 | NEW | no | yes | 0 | 0.9 |  | 32 | AllplanAttributes - Sicherheitsklasse: -; Sonnenschutztyp: Movable; g-Wert: 0,51
 | H2 Ebene +1 | WA-LB | 1155Wa 0000002523 | yes | Codetext | m² | Trockenbauarbeiten | Wand | Außenwand 7-Schalig | WA-LB | 0 | A | 3.75 | 1155HWa0000000826 | NEW | no | yes | 0 | 0.9 | no | 32 | no | Codetext | AllplanAttributes - Sicherheitsklasse: -; Sonnenschutztyp: Movable; g-Wert: 0,51
Konterlattung | H2 Ebene +1 | WA-KL | 1155Wa 0000002525 | yes |  | m² | Zimmer- und Holzbauarbeiten | Wand | Konterlattung | WA-KL |  |  | 3.75 | 1155HWa0000000826 | NEW | no | yes | 0 | 0.9 |  | 32 | AllplanAttributes - Sicherheitsklasse: -; Sonnenschutztyp: Movable; g-Wert: 0,51
Traglattung | H2 Ebene +1 | WA-TL | 1155Wa 0000002527 | yes |  | m² | Zimmer- und Holzbauarbeiten | Wand | Traglattung | WA-TL |  |  | 3.75 | 1155HWa0000000826 | NEW | no | yes | 0 | 0.9 |  | 32 | AllplanAttributes - Sicherheitsklasse: -; Sonnenschutztyp: Movable; g-Wert: 0,51
Holzschindel | H2 Ebene +1 | WA-HS | 1155Wa 0000002529 | yes |  | m² | Zimmer- und Holzbauarbeiten | Wand | Holzschindel | WA-HS |  |  | 3.75 | 1155HWa0000000826 | NEW | no | yes | 0 | 0.9 |  | 32 | AllplanAttributes - Sicherheitsklasse: -; Sonnenschutztyp: Movable; g-Wert: 0,51
2x Gipsfaserplatte | H2 Ebene +1 | WA-LB | 1155Wa 0000000898 | yes |  | m² | Trockenbauarbeiten | Wand | 2x Gipsfaserplatte | WA-LB |  |  | 3.75 | 1155HWa0000000824 | NEW | no | yes | 0 | 0.9 |  | 32 | AllplanAttributes - Sicherheitsklasse: -; Sonnenschutztyp: Movable; g-Wert: 0,51
Holzständer + Zwischendämmung | H2 Ebene +1 | WA-HD | 1155Wa 0000000966 | yes |  | m³ | Zimmer- und Holzbauarbeiten | Wand | Holzständer + Zwischendämmung | WA-HD |  |  | 3.75 | 1155HWa0000000824 | NEW | no | yes | 0 | 0.9 |  | 32 | AllplanAttributes - Sicherheitsklasse: -; Sonnenschutztyp: Movable; g-Wert: 0,51; ash W_laufende Nr. Statik: 2 (W 2.0/ 2.1/ 2.2)
Staffel + Zwischendämmung | H2 Ebene +1 | WA-DL | 1155Wa 0000000964 | yes |  | m³ | Zimmer- und Holzbauarbeiten | Wand | Staffel + Zwischendämmung | WA-DL |  |  | 3.75 | 1155HWa0000000824 | NEW | no | yes | 0 | 0.9 |  | 32 | AllplanAttributes - Sicherheitsklasse: -; Sonnenschutztyp: Movable; g-Wert: 0,51
 | H2 Ebene +1 | WA-LB | 1155Wa 0000000900 | yes | Codetext | m² | Trockenbauarbeiten | Wand | Außenwand 7-Schalig | WA-LB | 0 | A | 3.75 | 1155HWa0000000824 | NEW | no | yes | 0 | 0.9 | no | 32 | no | Codetext | AllplanAttributes - Sicherheitsklasse: -; Sonnenschutztyp: Movable; g-Wert: 0,51
Konterlattung | H2 Ebene +1 | WA-KL | 1155Wa 0000000902 | yes |  | m² | Zimmer- und Holzbauarbeiten | Wand | Konterlattung | WA-KL |  |  | 3.75 | 1155HWa0000000824 | NEW | no | yes | 0 | 0.9 |  | 32 | AllplanAttributes - Sicherheitsklasse: -; Sonnenschutztyp: Movable; g-Wert: 0,51
Traglattung | H2 Ebene +1 | WA-TL | 1155Wa 0000000904 | yes |  | m² | Zimmer- und Holzbauarbeiten | Wand | Traglattung | WA-TL |  |  | 3.75 | 1155HWa0000000824 | NEW | no | yes | 0 | 0.9 |  | 32 | AllplanAttributes - Sicherheitsklasse: -; Sonnenschutztyp: Movable; g-Wert: 0,51
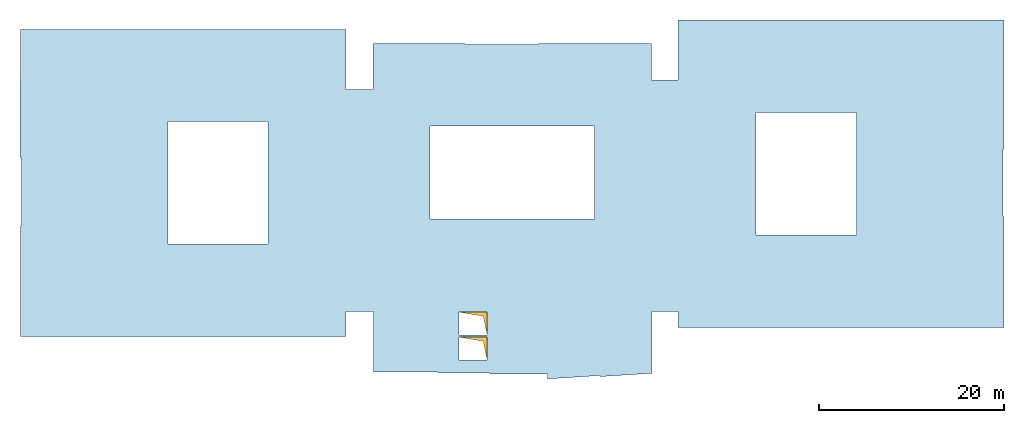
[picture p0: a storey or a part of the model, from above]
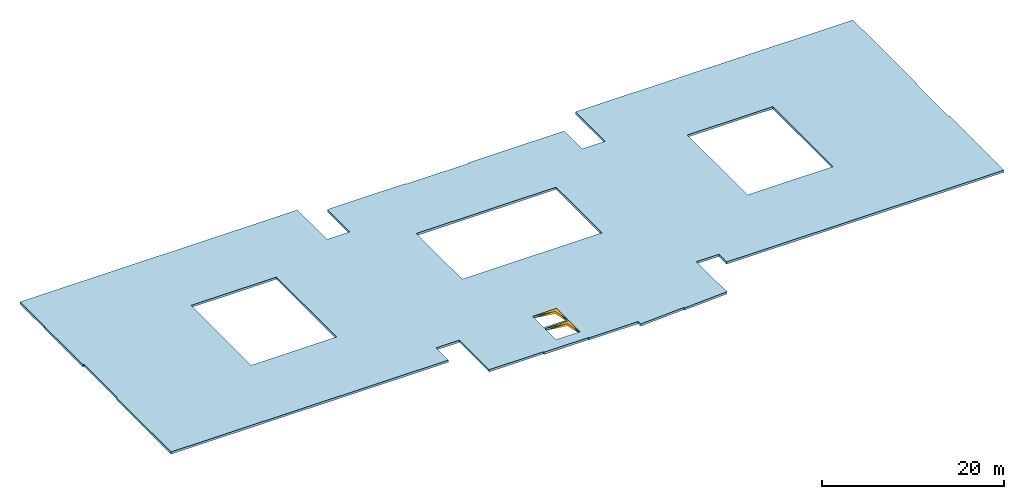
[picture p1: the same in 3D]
Properties of the parts of a building model (IFC4), part 60 of 80

# IfcWall (6826)
Name | In | Material | Allright_Bauteil_ID | 2D Interaktion | Codetext | Abrechnungsart | Gewerk | Objektname | Bezeichnung | AllplanAttributes, Material | Typ = SurfaceSpreadOfFlame | Brandschutzklasse | OKFF | P_ID | Status | LoadBearing | IsExternal | FireRating | ThermalTransmittance (W/K/m2) | Combustible | AcousticRating | Compartmentation | Reference
Holzschindel | H2 Ebene +1 | WA-HS | 1155Wa 0000000906 | yes |  | m² | Zimmer- und Holzbauarbeiten | Wand | Holzschindel | WA-HS |  |  | 3.75 | 1155HWa0000000824 | NEW | no | yes | 0 | 0.9 |  | 32 | AllplanAttributes - Sicherheitsklasse: -; Sonnenschutztyp: Movable; g-Wert: 0,51
2x Gipsfaserplatte | H2 Ebene +1 | WA-LB | 1155Wa 0000002831 | yes |  | m² | Trockenbauarbeiten | Wand | 2x Gipsfaserplatte | WA-LB |  |  | 3.75 | 1155HWa0000000815 | NEW | no | yes | 0 | 0.9 |  | 32 | AllplanAttributes - Sicherheitsklasse: -; Sonnenschutztyp: Movable; g-Wert: 0,51
Holzständer + Zwischendämmung | H2 Ebene +1 | WA-HD | 1155Wa 0000002833 | yes |  | m³ | Zimmer- und Holzbauarbeiten | Wand | Holzständer + Zwischendämmung | WA-HD |  |  | 3.75 | 1155HWa0000000815 | NEW | no | yes | 0 | 0.9 |  | 32 | AllplanAttributes - Sicherheitsklasse: -; Sonnenschutztyp: Movable; g-Wert: 0,51; ash W_laufende Nr. Statik: 2 (W 2.0/ 2.1/ 2.2)
Staffel + Zwischendämmung | H2 Ebene +1 | WA-DL | 1155Wa 0000002835 | yes |  | m³ | Zimmer- und Holzbauarbeiten | Wand | Staffel + Zwischendämmung | WA-DL |  |  | 3.75 | 1155HWa0000000815 | NEW | no | yes | 0 | 0.9 |  | 32 | AllplanAttributes - Sicherheitsklasse: -; Sonnenschutztyp: Movable; g-Wert: 0,51
 | H2 Ebene +1 | WA-LB | 1155Wa 0000002829 | yes | Codetext | m² | Trockenbauarbeiten | Wand | Außenwand 7-Schalig | WA-LB | 0 | A | 3.75 | 1155HWa0000000815 | NEW | no | yes | 0 | 0.9 | no | 32 | no | Codetext | AllplanAttributes - Sicherheitsklasse: -; Sonnenschutztyp: Movable; g-Wert: 0,51
Konterlattung | H2 Ebene +1 | WA-KL | 1155Wa 0000002827 | yes |  | m² | Zimmer- und Holzbauarbeiten | Wand | Konterlattung | WA-KL |  |  | 3.75 | 1155HWa0000000815 | NEW | no | yes | 0 | 0.9 |  | 32 | AllplanAttributes - Sicherheitsklasse: -; Sonnenschutztyp: Movable; g-Wert: 0,51
Traglattung | H2 Ebene +1 | WA-TL | 1155Wa 0000002825 | yes |  | m² | Zimmer- und Holzbauarbeiten | Wand | Traglattung | WA-TL |  |  | 3.75 | 1155HWa0000000815 | NEW | no | yes | 0 | 0.9 |  | 32 | AllplanAttributes - Sicherheitsklasse: -; Sonnenschutztyp: Movable; g-Wert: 0,51
Holzschindel | H2 Ebene +1 | WA-HS | 1155Wa 0000002823 | yes |  | m² | Zimmer- und Holzbauarbeiten | Wand | Holzschindel | WA-HS |  |  | 3.75 | 1155HWa0000000815 | NEW | no | yes | 0 | 0.9 |  | 32 | AllplanAttributes - Sicherheitsklasse: -; Sonnenschutztyp: Movable; g-Wert: 0,51
2x Gipsfaserplatte | H2 Ebene +1 | WA-LB | 1155Wa 0000002877 | yes |  | m² | Trockenbauarbeiten | Wand | 2x Gipsfaserplatte | WA-LB |  |  | 3.75 | 1155HWa0000002751 | NEW | no | yes | 0 | 0.9 |  | 32 | AllplanAttributes - Sicherheitsklasse: -; Sonnenschutztyp: Movable; g-Wert: 0,51
Holzständer + Zwischendämmung | H2 Ebene +1 | WA-HD | 1155Wa 0000002875 | yes |  | m³ | Zimmer- und Holzbauarbeiten | Wand | Holzständer + Zwischendämmung | WA-HD |  |  | 3.75 | 1155HWa0000002751 | NEW | no | yes | 0 | 0.9 |  | 32 | AllplanAttributes - Sicherheitsklasse: -; Sonnenschutztyp: Movable; g-Wert: 0,51
Staffel + Zwischendämmung | H2 Ebene +1 | WA-DL | 1155Wa 0000002873 | yes |  | m³ | Zimmer- und Holzbauarbeiten | Wand | Staffel + Zwischendämmung | WA-DL |  |  | 3.75 | 1155HWa0000002751 | NEW | no | yes | 0 | 0.9 |  | 32 | AllplanAttributes - Sicherheitsklasse: -; Sonnenschutztyp: Movable; g-Wert: 0,51
 | H2 Ebene +1 | WA-LB | 1155Wa 0000002871 | yes | Codetext | m² | Trockenbauarbeiten | Wand | Außenwand 7-Schalig | WA-LB | 0 | A | 3.75 | 1155HWa0000002751 | NEW | no | yes | 0 | 0.9 | no | 32 | no | Codetext | AllplanAttributes - Sicherheitsklasse: -; Sonnenschutztyp: Movable; g-Wert: 0,51
Konterlattung | H2 Ebene +1 | WA-KL | 1155Wa 0000002869 | yes |  | m² | Zimmer- und Holzbauarbeiten | Wand | Konterlattung | WA-KL |  |  | 3.75 | 1155HWa0000002751 | NEW | no | yes | 0 | 0.9 |  | 32 | AllplanAttributes - Sicherheitsklasse: -; Sonnenschutztyp: Movable; g-Wert: 0,51
Traglattung | H2 Ebene +1 | WA-TL | 1155Wa 0000002867 | yes |  | m² | Zimmer- und Holzbauarbeiten | Wand | Traglattung | WA-TL |  |  | 3.75 | 1155HWa0000002751 | NEW | no | yes | 0 | 0.9 |  | 32 | AllplanAttributes - Sicherheitsklasse: -; Sonnenschutztyp: Movable; g-Wert: 0,51
Holzschindel | H2 Ebene +1 | WA-HS | 1155Wa 0000002865 | yes |  | m² | Zimmer- und Holzbauarbeiten | Wand | Holzschindel | WA-HS |  |  | 3.75 | 1155HWa0000002751 | NEW | no | yes | 0 | 0.9 |  | 32 | AllplanAttributes - Sicherheitsklasse: -; Sonnenschutztyp: Movable; g-Wert: 0,51
2x Gipsfaserplatte | H2 Ebene +1 | WA-LB | 1155Wa 0000002911 | yes |  | m² | Trockenbauarbeiten | Wand | 2x Gipsfaserplatte | WA-LB |  |  | 3.75 | 1155HWa0000002879 | NEW | no | yes | 0 | 0.9 |  | 32 | AllplanAttributes - Sicherheitsklasse: -; Sonnenschutztyp: Movable; g-Wert: 0,51
Holzständer + Zwischendämmung | H2 Ebene +1 | WA-HD | 1155Wa 0000002913 | yes |  | m³ | Zimmer- und Holzbauarbeiten | Wand | Holzständer + Zwischendämmung | WA-HD |  |  | 3.75 | 1155HWa0000002879 | NEW | no | yes | 0 | 0.9 |  | 32 | AllplanAttributes - Sicherheitsklasse: -; Sonnenschutztyp: Movable; g-Wert: 0,51
Staffel + Zwischendämmung | H2 Ebene +1 | WA-DL | 1155Wa 0000002915 | yes |  | m³ | Zimmer- und Holzbauarbeiten | Wand | Staffel + Zwischendämmung | WA-DL |  |  | 3.75 | 1155HWa0000002879 | NEW | no | yes | 0 | 0.9 |  | 32 | AllplanAttributes - Sicherheitsklasse: -; Sonnenschutztyp: Movable; g-Wert: 0,51
 | H2 Ebene +1 | WA-LB | 1155Wa 0000002917 | yes | Codetext | m² | Trockenbauarbeiten | Wand | Außenwand 7-Schalig | WA-LB | 0 | A | 3.75 | 1155HWa0000002879 | NEW | no | yes | 0 | 0.9 | no | 32 | no | Codetext | AllplanAttributes - Sicherheitsklasse: -; Sonnenschutztyp: Movable; g-Wert: 0,51
Konterlattung | H2 Ebene +1 | WA-KL | 1155Wa 0000002919 | yes |  | m² | Zimmer- und Holzbauarbeiten | Wand | Konterlattung | WA-KL |  |  | 3.75 | 1155HWa0000002879 | NEW | no | yes | 0 | 0.9 |  | 32 | AllplanAttributes - Sicherheitsklasse: -; Sonnenschutztyp: Movable; g-Wert: 0,51
Traglattung | H2 Ebene +1 | WA-TL | 1155Wa 0000002921 | yes |  | m² | Zimmer- und Holzbauarbeiten | Wand | Traglattung | WA-TL |  |  | 3.75 | 1155HWa0000002879 | NEW | no | yes | 0 | 0.9 |  | 32 | AllplanAttributes - Sicherheitsklasse: -; Sonnenschutztyp: Movable; g-Wert: 0,51
Holzschindel | H2 Ebene +1 | WA-HS | 1155Wa 0000002923 | yes |  | m² | Zimmer- und Holzbauarbeiten | Wand | Holzschindel | WA-HS |  |  | 3.75 | 1155HWa0000002879 | NEW | no | yes | 0 | 0.9 |  | 32 | AllplanAttributes - Sicherheitsklasse: -; Sonnenschutztyp: Movable; g-Wert: 0,51
 | H2 Ebene +1 | WA-LB | 1155Wa 0000002907 | yes | Codetext | m² | Trockenbauarbeiten | Wand | Außenwand 7-Schalig | WA-LB | 0 | A | 3.75 | 1155HWa0000002845 | NEW | no | yes | 0 | 0.9 | no | 32 | no | Codetext | AllplanAttributes - Sicherheitsklasse: -; Sonnenschutztyp: Movable; g-Wert: 0,51
 | H2 Ebene +1 | WA-DL | 1155Wa 0000002903 | yes | Codetext | m³ | Zimmer- und Holzbauarbeiten | Wand | Außenwand 7-Schalig | WA-DL | 0 | A | 3.75 | 1155HWa0000002845 | NEW | no | yes | 0 | 0.9 | no | 32 | no | Codetext | AllplanAttributes - Sicherheitsklasse: -; Sonnenschutztyp: Movable; g-Wert: 0,51
 | H2 Ebene +1 | WA-DL | 1155Wa 0000002899 | yes | Codetext | m³ | Zimmer- und Holzbauarbeiten | Wand | Außenwand 7-Schalig | WA-DL | 0 | A | 3.75 | 1155HWa0000002845 | NEW | no | yes | 0 | 0.9 | no | 32 | no | Codetext | AllplanAttributes - Sicherheitsklasse: -; Sonnenschutztyp: Movable; g-Wert: 0,51
 | H2 Ebene +1 | WA-LB | 1155Wa 0000002895 | yes | Codetext | m² | Trockenbauarbeiten | Wand | Außenwand 7-Schalig | WA-LB | 0 | A | 3.75 | 1155HWa0000002845 | NEW | no | yes | 0 | 0.9 | no | 32 | no | Codetext | AllplanAttributes - Sicherheitsklasse: -; Sonnenschutztyp: Movable; g-Wert: 0,51
 | H2 Ebene +1 | WA-KL | 1155Wa 0000002891 | yes | Codetext | m² | Zimmer- und Holzbauarbeiten | Wand | Außenwand 7-Schalig | WA-KL | 0 | A | 3.75 | 1155HWa0000002845 | NEW | no | yes | 0 | 0.9 | no | 32 | no | Codetext | AllplanAttributes - Sicherheitsklasse: -; Sonnenschutztyp: Movable; g-Wert: 0,51
 | H2 Ebene +1 | WA-TL | 1155Wa 0000002887 | yes | Codetext | m² | Zimmer- und Holzbauarbeiten | Wand | Außenwand 7-Schalig | WA-TL | 0 | A | 3.75 | 1155HWa0000002845 | NEW | no | yes | 0 | 0.9 | no | 32 | no | Codetext | AllplanAttributes - Sicherheitsklasse: -; Sonnenschutztyp: Movable; g-Wert: 0,51
 | H2 Ebene +1 | WA-HS | 1155Wa 0000002883 | yes | Codetext | m² | Zimmer- und Holzbauarbeiten | Wand | Außenwand 7-Schalig | WA-HS | 0 | A | 3.75 | 1155HWa0000002845 | NEW | no | yes | 0 | 0.9 | no | 32 | no | Codetext | AllplanAttributes - Sicherheitsklasse: -; Sonnenschutztyp: Movable; g-Wert: 0,51
 | H2 Ebene +1 | WA-LB | 1155Wa 0000002926 | yes | Codetext | m² | Trockenbauarbeiten | Wand | Außenwand 7-Schalig | WA-LB | 0 | A | 3.75 | 1155HWa0000002909 | NEW | no | yes | 0 | 0.9 | no | 32 | no | Codetext | AllplanAttributes - Sicherheitsklasse: -; Sonnenschutztyp: Movable; g-Wert: 0,51
 | H2 Ebene +1 | WA-HD | 1155Wa 0000002928 | yes | Codetext | m³ | Zimmer- und Holzbauarbeiten | Wand | Außenwand 7-Schalig | WA-HD | 0 | A | 3.75 | 1155HWa0000002909 | NEW | no | yes | 0 | 0.9 | no | 32 | no | Codetext | AllplanAttributes - Sicherheitsklasse: -; Sonnenschutztyp: Movable; g-Wert: 0,51
 | H2 Ebene +1 | WA-DL | 1155Wa 0000002939 | yes | Codetext | m³ | Zimmer- und Holzbauarbeiten | Wand | Außenwand 7-Schalig | WA-DL | 0 | A | 3.75 | 1155HWa0000002909 | NEW | no | yes | 0 | 0.9 | no | 32 | no | Codetext | AllplanAttributes - Sicherheitsklasse: -; Sonnenschutztyp: Movable; g-Wert: 0,51
 | H2 Ebene +1 | WA-LB | 1155Wa 0000002937 | yes | Codetext | m² | Trockenbauarbeiten | Wand | Außenwand 7-Schalig | WA-LB | 0 | A | 3.75 | 1155HWa0000002909 | NEW | no | yes | 0 | 0.9 | no | 32 | no | Codetext | AllplanAttributes - Sicherheitsklasse: -; Sonnenschutztyp: Movable; g-Wert: 0,51
 | H2 Ebene +1 | WA-KL | 1155Wa 0000002935 | yes | Codetext | m² | Zimmer- und Holzbauarbeiten | Wand | Außenwand 7-Schalig | WA-KL | 0 | A | 3.75 | 1155HWa0000002909 | NEW | no | yes | 0 | 0.9 | no | 32 | no | Codetext | AllplanAttributes - Sicherheitsklasse: -; Sonnenschutztyp: Movable; g-Wert: 0,51
 | H2 Ebene +1 | WA-TL | 1155Wa 0000002933 | yes | Codetext | m² | Zimmer- und Holzbauarbeiten | Wand | Außenwand 7-Schalig | WA-TL | 0 | A | 3.75 | 1155HWa0000002909 | NEW | no | yes | 0 | 0.9 | no | 32 | no | Codetext | AllplanAttributes - Sicherheitsklasse: -; Sonnenschutztyp: Movable; g-Wert: 0,51
 | H2 Ebene +1 | WA-HS | 1155Wa 0000002931 | yes | Codetext | m² | Zimmer- und Holzbauarbeiten | Wand | Außenwand 7-Schalig | WA-HS | 0 | A | 3.75 | 1155HWa0000002909 | NEW | no | yes | 0 | 0.9 | no | 32 | no | Codetext | AllplanAttributes - Sicherheitsklasse: -; Sonnenschutztyp: Movable; g-Wert: 0,51
 | H2 Ebene +1 | WA-LB | 1155Wa 0000003057 | yes | Codetext | m² | Trockenbauarbeiten | Wand | Außenwand 7-Schalig | WA-LB | 0 | A | 3.75 | 1155HWa0000002994 | NEW | no | yes | 0 | 0.9 | no | 32 | no | Codetext | AllplanAttributes - Sicherheitsklasse: -; Sonnenschutztyp: Movable; g-Wert: 0,51
 | H2 Ebene +1 | WA-HD | 1155Wa 0000003053 | yes | Codetext | m³ | Zimmer- und Holzbauarbeiten | Wand | Außenwand 7-Schalig | WA-HD | 0 | A | 3.75 | 1155HWa0000002994 | NEW | no | yes | 0 | 0.9 | no | 32 | no | Codetext | AllplanAttributes - Sicherheitsklasse: -; Sonnenschutztyp: Movable; g-Wert: 0,51
 | H2 Ebene +1 | WA-DL | 1155Wa 0000003049 | yes | Codetext | m³ | Zimmer- und Holzbauarbeiten | Wand | Außenwand 7-Schalig | WA-DL | 0 | A | 3.75 | 1155HWa0000002994 | NEW | no | yes | 0 | 0.9 | no | 32 | no | Codetext | AllplanAttributes - Sicherheitsklasse: -; Sonnenschutztyp: Movable; g-Wert: 0,51
 | H2 Ebene +1 | WA-LB | 1155Wa 0000003045 | yes | Codetext | m² | Trockenbauarbeiten | Wand | Außenwand 7-Schalig | WA-LB | 0 | A | 3.75 | 1155HWa0000002994 | NEW | no | yes | 0 | 0.9 | no | 32 | no | Codetext | AllplanAttributes - Sicherheitsklasse: -; Sonnenschutztyp: Movable; g-Wert: 0,51
 | H2 Ebene +1 | WA-KL | 1155Wa 0000003041 | yes | Codetext | m² | Zimmer- und Holzbauarbeiten | Wand | Außenwand 7-Schalig | WA-KL | 0 | A | 3.75 | 1155HWa0000002994 | NEW | no | yes | 0 | 0.9 | no | 32 | no | Codetext | AllplanAttributes - Sicherheitsklasse: -; Sonnenschutztyp: Movable; g-Wert: 0,51
 | H2 Ebene +1 | WA-TL | 1155Wa 0000003037 | yes | Codetext | m² | Zimmer- und Holzbauarbeiten | Wand | Außenwand 7-Schalig | WA-TL | 0 | A | 3.75 | 1155HWa0000002994 | NEW | no | yes | 0 | 0.9 | no | 32 | no | Codetext | AllplanAttributes - Sicherheitsklasse: -; Sonnenschutztyp: Movable; g-Wert: 0,51
 | H2 Ebene +1 | WA-HS | 1155Wa 0000003033 | yes | Codetext | m² | Zimmer- und Holzbauarbeiten | Wand | Außenwand 7-Schalig | WA-HS | 0 | A | 3.75 | 1155HWa0000002994 | NEW | no | yes | 0 | 0.9 | no | 32 | no | Codetext | AllplanAttributes - Sicherheitsklasse: -; Sonnenschutztyp: Movable; g-Wert: 0,51
2x Gipsfaserplatte | H2 Ebene +1 | WA-LB | 1155Wa 0000003128 | yes |  | m² | Trockenbauarbeiten | Wand | 2x Gipsfaserplatte | WA-LB |  |  | 3.75 | 1155HWa0000003029 | NEW | no | yes | 0 | 0.9 |  | 32 | AllplanAttributes - Sicherheitsklasse: -; Sonnenschutztyp: Movable; g-Wert: 0,51
Holzständer + Zwischendämmung | H2 Ebene +1 | WA-HD | 1155Wa 0000003130 | yes |  | m³ | Zimmer- und Holzbauarbeiten | Wand | Holzständer + Zwischendämmung | WA-HD |  |  | 3.75 | 1155HWa0000003029 | NEW | no | yes | 0 | 0.9 |  | 32 | AllplanAttributes - Sicherheitsklasse: -; Sonnenschutztyp: Movable; g-Wert: 0,51
Staffel + Zwischendämmung | H2 Ebene +1 | WA-DL | 1155Wa 0000003132 | yes |  | m³ | Zimmer- und Holzbauarbeiten | Wand | Staffel + Zwischendämmung | WA-DL |  |  | 3.75 | 1155HWa0000003029 | NEW | no | yes | 0 | 0.9 |  | 32 | AllplanAttributes - Sicherheitsklasse: -; Sonnenschutztyp: Movable; g-Wert: 0,51
 | H2 Ebene +1 | WA-LB | 1155Wa 0000003134 | yes | Codetext | m² | Trockenbauarbeiten | Wand | Außenwand 7-Schalig | WA-LB | 0 | A | 3.75 | 1155HWa0000003029 | NEW | no | yes | 0 | 0.9 | no | 32 | no | Codetext | AllplanAttributes - Sicherheitsklasse: -; Sonnenschutztyp: Movable; g-Wert: 0,51
Konterlattung | H2 Ebene +1 | WA-KL | 1155Wa 0000003136 | yes |  | m² | Zimmer- und Holzbauarbeiten | Wand | Konterlattung | WA-KL |  |  | 3.75 | 1155HWa0000003029 | NEW | no | yes | 0 | 0.9 |  | 32 | AllplanAttributes - Sicherheitsklasse: -; Sonnenschutztyp: Movable; g-Wert: 0,51
Traglattung | H2 Ebene +1 | WA-TL | 1155Wa 0000003138 | yes |  | m² | Zimmer- und Holzbauarbeiten | Wand | Traglattung | WA-TL |  |  | 3.75 | 1155HWa0000003029 | NEW | no | yes | 0 | 0.9 |  | 32 | AllplanAttributes - Sicherheitsklasse: -; Sonnenschutztyp: Movable; g-Wert: 0,51
Holzschindel | H2 Ebene +1 | WA-HS | 1155Wa 0000003140 | yes |  | m² | Zimmer- und Holzbauarbeiten | Wand | Holzschindel | WA-HS |  |  | 3.75 | 1155HWa0000003029 | NEW | no | yes | 0 | 0.9 |  | 32 | AllplanAttributes - Sicherheitsklasse: -; Sonnenschutztyp: Movable; g-Wert: 0,51
 | H2 Ebene +1 | WA-LB | 1155Wa 0000003947 | yes | Codetext | m² | Trockenbauarbeiten | Wand | Außenwand 7-Schalig | WA-LB | 0 | A | 3.75 | 1155HWa0000003164 | NEW | no | yes | 0 | 0.9 | no | 32 | no | Codetext | AllplanAttributes - Sicherheitsklasse: -; Sonnenschutztyp: Movable; g-Wert: 0,51
 | H2 Ebene +1 | WA-DL | 1155Wa 0000003957 | yes | Codetext | m³ | Zimmer- und Holzbauarbeiten | Wand | Außenwand 7-Schalig | WA-DL | 0 | A | 3.75 | 1155HWa0000003164 | NEW | no | yes | 0 | 0.9 | no | 32 | no | Codetext | AllplanAttributes - ash D_Detailverweis: DT D; ash D_Plannummer: D1851; Sicherheitsklasse: -; Sonnenschutztyp: Movable; g-Wert: 0,51; ash W_laufende Nr. Statik: 2 (W 2.0/ 2.1/ 2.2)
 | H2 Ebene +1 | WA-DL | 1155Wa 0000003966 | yes | Codetext | m³ | Zimmer- und Holzbauarbeiten | Wand | Außenwand 7-Schalig | WA-DL | 0 | A | 3.75 | 1155HWa0000003164 | NEW | no | yes | 0 | 0.9 | no | 32 | no | Codetext | AllplanAttributes - Sicherheitsklasse: -; Sonnenschutztyp: Movable; g-Wert: 0,51
 | H2 Ebene +1 | WA-LB | 1155Wa 0000003976 | yes | Codetext | m² | Trockenbauarbeiten | Wand | Außenwand 7-Schalig | WA-LB | 0 | A | 3.75 | 1155HWa0000003164 | NEW | no | yes | 0 | 0.9 | no | 32 | no | Codetext | AllplanAttributes - Sicherheitsklasse: -; Sonnenschutztyp: Movable; g-Wert: 0,51
 | H2 Ebene +1 | WA-KL | 1155Wa 0000003986 | yes | Codetext | m² | Zimmer- und Holzbauarbeiten | Wand | Außenwand 7-Schalig | WA-KL | 0 | A | 3.75 | 1155HWa0000003164 | NEW | no | yes | 0 | 0.9 | no | 32 | no | Codetext | AllplanAttributes - Sicherheitsklasse: -; Sonnenschutztyp: Movable; g-Wert: 0,51
 | H2 Ebene +1 | WA-TL | 1155Wa 0000003996 | yes | Codetext | m² | Zimmer- und Holzbauarbeiten | Wand | Außenwand 7-Schalig | WA-TL | 0 | A | 3.75 | 1155HWa0000003164 | NEW | no | yes | 0 | 0.9 | no | 32 | no | Codetext | AllplanAttributes - Sicherheitsklasse: -; Sonnenschutztyp: Movable; g-Wert: 0,51
 | H2 Ebene +1 | WA-HS | 1155Wa 0000004006 | yes | Codetext | m² | Zimmer- und Holzbauarbeiten | Wand | Außenwand 7-Schalig | WA-HS | 0 | A | 3.75 | 1155HWa0000003164 | NEW | no | yes | 0 | 0.9 | no | 32 | no | Codetext | AllplanAttributes - Sicherheitsklasse: -; Sonnenschutztyp: Movable; g-Wert: 0,51
 | H2 Ebene +1 | WA-LB | 1155Wa 0000004443 | yes | Codetext | m² | Trockenbauarbeiten | Wand | Außenwand 7-Schalig | WA-LB | 0 | A | 3.75 | 1155HWa0000004384 | NEW | no | yes | 0 | 0.9 | no | 32 | no | Codetext | AllplanAttributes - Sicherheitsklasse: -; Sonnenschutztyp: Movable; g-Wert: 0,51
 | H2 Ebene +1 | WA-DL | 1155Wa 0000004441 | yes | Codetext | m³ | Zimmer- und Holzbauarbeiten | Wand | Außenwand 7-Schalig | WA-DL | 0 | A | 3.75 | 1155HWa0000004384 | NEW | no | yes | 0 | 0.9 | no | 32 | no | Codetext | AllplanAttributes - ash D_Detailverweis: DT D; ash D_Plannummer: D1851; Sicherheitsklasse: -; Sonnenschutztyp: Movable; g-Wert: 0,51; ash W_laufende Nr. Statik: 2 (W 2.0/ 2.1/ 2.2)
 | H2 Ebene +1 | WA-DL | 1155Wa 0000004439 | yes | Codetext | m³ | Zimmer- und Holzbauarbeiten | Wand | Außenwand 7-Schalig | WA-DL | 0 | A | 3.75 | 1155HWa0000004384 | NEW | no | yes | 0 | 0.9 | no | 32 | no | Codetext | AllplanAttributes - Sicherheitsklasse: -; Sonnenschutztyp: Movable; g-Wert: 0,51
 | H2 Ebene +1 | WA-LB | 1155Wa 0000004437 | yes | Codetext | m² | Trockenbauarbeiten | Wand | Außenwand 7-Schalig | WA-LB | 0 | A | 3.75 | 1155HWa0000004384 | NEW | no | yes | 0 | 0.9 | no | 32 | no | Codetext | AllplanAttributes - Sicherheitsklasse: -; Sonnenschutztyp: Movable; g-Wert: 0,51
 | H2 Ebene +1 | WA-KL | 1155Wa 0000004435 | yes | Codetext | m² | Zimmer- und Holzbauarbeiten | Wand | Außenwand 7-Schalig | WA-KL | 0 | A | 3.75 | 1155HWa0000004384 | NEW | no | yes | 0 | 0.9 | no | 32 | no | Codetext | AllplanAttributes - Sicherheitsklasse: -; Sonnenschutztyp: Movable; g-Wert: 0,51
 | H2 Ebene +1 | WA-TL | 1155Wa 0000004433 | yes | Codetext | m² | Zimmer- und Holzbauarbeiten | Wand | Außenwand 7-Schalig | WA-TL | 0 | A | 3.75 | 1155HWa0000004384 | NEW | no | yes | 0 | 0.9 | no | 32 | no | Codetext | AllplanAttributes - Sicherheitsklasse: -; Sonnenschutztyp: Movable; g-Wert: 0,51
 | H2 Ebene +1 | WA-HS | 1155Wa 0000004431 | yes | Codetext | m² | Zimmer- und Holzbauarbeiten | Wand | Außenwand 7-Schalig | WA-HS | 0 | A | 3.75 | 1155HWa0000004384 | NEW | no | yes | 0 | 0.9 | no | 32 | no | Codetext | AllplanAttributes - Sicherheitsklasse: -; Sonnenschutztyp: Movable; g-Wert: 0,51
2x Gipsfaserplatte | H2 Ebene +1 | WA-LB | 1155Wa 0000004471 | yes |  | m² | Trockenbauarbeiten | Wand | 2x Gipsfaserplatte | WA-LB |  |  | 3.75 | 1155HWa0000004382 | NEW | no | yes | 0 | 0.9 |  | 32 | AllplanAttributes - Sicherheitsklasse: -; Sonnenschutztyp: Movable; g-Wert: 0,51
Holzständer + Zwischendämmung | H2 Ebene +1 | WA-DL | 1155Wa 0000004469 | yes |  | m³ | Zimmer- und Holzbauarbeiten | Wand | Holzständer + Zwischendämmung | WA-DL |  |  | 3.75 | 1155HWa0000004382 | NEW | no | yes | 0 | 0.9 |  | 32 | AllplanAttributes - Sicherheitsklasse: -; Sonnenschutztyp: Movable; g-Wert: 0,51; ash W_laufende Nr. Statik: 2 (W 2.0/ 2.1/ 2.2)
Staffel + Zwischendämmung | H2 Ebene +1 | WA-DL | 1155Wa 0000004467 | yes |  | m³ | Zimmer- und Holzbauarbeiten | Wand | Staffel + Zwischendämmung | WA-DL |  |  | 3.75 | 1155HWa0000004382 | NEW | no | yes | 0 | 0.9 |  | 32 | AllplanAttributes - Sicherheitsklasse: -; Sonnenschutztyp: Movable; g-Wert: 0,51
 | H2 Ebene +1 | WA-LB | 1155Wa 0000004465 | yes | Codetext | m² | Trockenbauarbeiten | Wand | Außenwand 7-Schalig | WA-LB | 0 | A | 3.75 | 1155HWa0000004382 | NEW | no | yes | 0 | 0.9 | no | 32 | no | Codetext | AllplanAttributes - Sicherheitsklasse: -; Sonnenschutztyp: Movable; g-Wert: 0,51
Konterlattung | H2 Ebene +1 | WA-KL | 1155Wa 0000004463 | yes |  | m² | Zimmer- und Holzbauarbeiten | Wand | Konterlattung | WA-KL |  |  | 3.75 | 1155HWa0000004382 | NEW | no | yes | 0 | 0.9 |  | 32 | AllplanAttributes - Sicherheitsklasse: -; Sonnenschutztyp: Movable; g-Wert: 0,51
Traglattung | H2 Ebene +1 | WA-TL | 1155Wa 0000004461 | yes |  | m² | Zimmer- und Holzbauarbeiten | Wand | Traglattung | WA-TL |  |  | 3.75 | 1155HWa0000004382 | NEW | no | yes | 0 | 0.9 |  | 32 | AllplanAttributes - Sicherheitsklasse: -; Sonnenschutztyp: Movable; g-Wert: 0,51
Holzschindel | H2 Ebene +1 | WA-HS | 1155Wa 0000004459 | yes |  | m² | Zimmer- und Holzbauarbeiten | Wand | Holzschindel | WA-HS |  |  | 3.75 | 1155HWa0000004382 | NEW | no | yes | 0 | 0.9 |  | 32 | AllplanAttributes - Sicherheitsklasse: -; Sonnenschutztyp: Movable; g-Wert: 0,51
 | H2 Ebene +1 | WA-LB | 1155Wa 0000004803 | yes | Codetext | m² | Trockenbauarbeiten | Wand | Außenwand 7-Schalig | WA-LB | 0 | A | 3.75 | 1155HWa0000003165 | NEW | no | yes | 0 | 0.9 | no | 32 | no | Codetext | AllplanAttributes - Sicherheitsklasse: -; Sonnenschutztyp: Movable; g-Wert: 0,51
 | H2 Ebene +1 | WA-DL | 1155Wa 0000004805 | yes | Codetext | m³ | Zimmer- und Holzbauarbeiten | Wand | Außenwand 7-Schalig | WA-DL | 0 | A | 3.75 | 1155HWa0000003165 | NEW | no | yes | 0 | 0.9 | no | 32 | no | Codetext | AllplanAttributes - Sicherheitsklasse: -; Sonnenschutztyp: Movable; g-Wert: 0,51; ash W_laufende Nr. Statik: 2 (W 2.0/ 2.1/ 2.2)
 | H2 Ebene +1 | WA-DL | 1155Wa 0000004807 | yes | Codetext | m³ | Zimmer- und Holzbauarbeiten | Wand | Außenwand 7-Schalig | WA-DL | 0 | A | 3.75 | 1155HWa0000003165 | NEW | no | yes | 0 | 0.9 | no | 32 | no | Codetext | AllplanAttributes - Sicherheitsklasse: -; Sonnenschutztyp: Movable; g-Wert: 0,51
 | H2 Ebene +1 | WA-LB | 1155Wa 0000004809 | yes | Codetext | m² | Trockenbauarbeiten | Wand | Außenwand 7-Schalig | WA-LB | 0 | A | 3.75 | 1155HWa0000003165 | NEW | no | yes | 0 | 0.9 | no | 32 | no | Codetext | AllplanAttributes - Sicherheitsklasse: -; Sonnenschutztyp: Movable; g-Wert: 0,51
 | H2 Ebene +1 | WA-KL | 1155Wa 0000004811 | yes | Codetext | m² | Zimmer- und Holzbauarbeiten | Wand | Außenwand 7-Schalig | WA-KL | 0 | A | 3.75 | 1155HWa0000003165 | NEW | no | yes | 0 | 0.9 | no | 32 | no | Codetext | AllplanAttributes - Sicherheitsklasse: -; Sonnenschutztyp: Movable; g-Wert: 0,51
 | H2 Ebene +1 | WA-TL | 1155Wa 0000004813 | yes | Codetext | m² | Zimmer- und Holzbauarbeiten | Wand | Außenwand 7-Schalig | WA-TL | 0 | A | 3.75 | 1155HWa0000003165 | NEW | no | yes | 0 | 0.9 | no | 32 | no | Codetext | AllplanAttributes - Sicherheitsklasse: -; Sonnenschutztyp: Movable; g-Wert: 0,51
 | H2 Ebene +1 | WA-HS | 1155Wa 0000004815 | yes | Codetext | m² | Zimmer- und Holzbauarbeiten | Wand | Außenwand 7-Schalig | WA-HS | 0 | A | 3.75 | 1155HWa0000003165 | NEW | no | yes | 0 | 0.9 | no | 32 | no | Codetext | AllplanAttributes - Sicherheitsklasse: -; Sonnenschutztyp: Movable; g-Wert: 0,51
 | H2 Ebene +1 | WA-LB | 1155Wa 0000004406 | yes | Codetext | m² | Trockenbauarbeiten | Wand | Außenwand 7-Schalig | WA-LB | 0 | A | 3.75 | 1155HWa0000004287 | NEW | no | yes | 0 | 0.9 | no | 32 | no | Codetext | AllplanAttributes - Sicherheitsklasse: -; Sonnenschutztyp: Movable; g-Wert: 0,51
 | H2 Ebene +1 | WA-DL | 1155Wa 0000004410 | yes | Codetext | m³ | Zimmer- und Holzbauarbeiten | Wand | Außenwand 7-Schalig | WA-DL | 0 | A | 3.75 | 1155HWa0000004287 | NEW | no | yes | 0 | 0.9 | no | 32 | no | Codetext | AllplanAttributes - ash D_Detailverweis: DT D; ash D_Plannummer: D1851; Sicherheitsklasse: -; Sonnenschutztyp: Movable; g-Wert: 0,51; ash W_laufende Nr. Statik: 2 (W 2.0/ 2.1/ 2.2)
 | H2 Ebene +1 | WA-DL | 1155Wa 0000004402 | yes | Codetext | m³ | Zimmer- und Holzbauarbeiten | Wand | Außenwand 7-Schalig | WA-DL | 0 | A | 3.75 | 1155HWa0000004287 | NEW | no | yes | 0 | 0.9 | no | 32 | no | Codetext | AllplanAttributes - Sicherheitsklasse: -; Sonnenschutztyp: Movable; g-Wert: 0,51
 | H2 Ebene +1 | WA-LB | 1155Wa 0000004398 | yes | Codetext | m² | Trockenbauarbeiten | Wand | Außenwand 7-Schalig | WA-LB | 0 | A | 3.75 | 1155HWa0000004287 | NEW | no | yes | 0 | 0.9 | no | 32 | no | Codetext | AllplanAttributes - Sicherheitsklasse: -; Sonnenschutztyp: Movable; g-Wert: 0,51
 | H2 Ebene +1 | WA-KL | 1155Wa 0000004394 | yes | Codetext | m² | Zimmer- und Holzbauarbeiten | Wand | Außenwand 7-Schalig | WA-KL | 0 | A | 3.75 | 1155HWa0000004287 | NEW | no | yes | 0 | 0.9 | no | 32 | no | Codetext | AllplanAttributes - Sicherheitsklasse: -; Sonnenschutztyp: Movable; g-Wert: 0,51
 | H2 Ebene +1 | WA-TL | 1155Wa 0000004390 | yes | Codetext | m² | Zimmer- und Holzbauarbeiten | Wand | Außenwand 7-Schalig | WA-TL | 0 | A | 3.75 | 1155HWa0000004287 | NEW | no | yes | 0 | 0.9 | no | 32 | no | Codetext | AllplanAttributes - Sicherheitsklasse: -; Sonnenschutztyp: Movable; g-Wert: 0,51
 | H2 Ebene +1 | WA-HS | 1155Wa 0000004416 | yes | Codetext | m² | Zimmer- und Holzbauarbeiten | Wand | Außenwand 7-Schalig | WA-HS | 0 | A | 3.75 | 1155HWa0000004287 | NEW | no | yes | 0 | 0.9 | no | 32 | no | Codetext | AllplanAttributes - Sicherheitsklasse: -; Sonnenschutztyp: Movable; g-Wert: 0,51
 | H2 Ebene +1 | WA-LB | 1155Wa 0000004611 | yes | Codetext | m² | Trockenbauarbeiten | Wand | Außenwand 7-Schalig | WA-LB | 0 | A | 3.75 | 1155HWa0000004228 | NEW | no | yes | 0 | 0.9 | no | 32 | no | Codetext | AllplanAttributes - Sicherheitsklasse: -; Sonnenschutztyp: Movable; g-Wert: 0,51
 | H2 Ebene +1 | WA-DL | 1155Wa 0000004607 | yes | Codetext | m³ | Zimmer- und Holzbauarbeiten | Wand | Außenwand 7-Schalig | WA-DL | 0 | A | 3.75 | 1155HWa0000004228 | NEW | no | yes | 0 | 0.9 | no | 32 | no | Codetext | AllplanAttributes - ash D_Detailverweis: DT D; ash D_Plannummer: D1851; Sicherheitsklasse: -; Sonnenschutztyp: Movable; g-Wert: 0,51; ash W_laufende Nr. Statik: 2 (W 2.0/ 2.1/ 2.2)
 | H2 Ebene +1 | WA-DL | 1155Wa 0000004603 | yes | Codetext | m³ | Zimmer- und Holzbauarbeiten | Wand | Außenwand 7-Schalig | WA-DL | 0 | A | 3.75 | 1155HWa0000004228 | NEW | no | yes | 0 | 0.9 | no | 32 | no | Codetext | AllplanAttributes - Sicherheitsklasse: -; Sonnenschutztyp: Movable; g-Wert: 0,51
 | H2 Ebene +1 | WA-LB | 1155Wa 0000004599 | yes | Codetext | m² | Trockenbauarbeiten | Wand | Außenwand 7-Schalig | WA-LB | 0 | A | 3.75 | 1155HWa0000004228 | NEW | no | yes | 0 | 0.9 | no | 32 | no | Codetext | AllplanAttributes - Sicherheitsklasse: -; Sonnenschutztyp: Movable; g-Wert: 0,51
 | H2 Ebene +1 | WA-KL | 1155Wa 0000004595 | yes | Codetext | m² | Zimmer- und Holzbauarbeiten | Wand | Außenwand 7-Schalig | WA-KL | 0 | A | 3.75 | 1155HWa0000004228 | NEW | no | yes | 0 | 0.9 | no | 32 | no | Codetext | AllplanAttributes - Sicherheitsklasse: -; Sonnenschutztyp: Movable; g-Wert: 0,51
 | H2 Ebene +1 | WA-TL | 1155Wa 0000004591 | yes | Codetext | m² | Zimmer- und Holzbauarbeiten | Wand | Außenwand 7-Schalig | WA-TL | 0 | A | 3.75 | 1155HWa0000004228 | NEW | no | yes | 0 | 0.9 | no | 32 | no | Codetext | AllplanAttributes - Sicherheitsklasse: -; Sonnenschutztyp: Movable; g-Wert: 0,51
 | H2 Ebene +1 | WA-HS | 1155Wa 0000004587 | yes | Codetext | m² | Zimmer- und Holzbauarbeiten | Wand | Außenwand 7-Schalig | WA-HS | 0 | A | 3.75 | 1155HWa0000004228 | NEW | no | yes | 0 | 0.9 | no | 32 | no | Codetext | AllplanAttributes - Sicherheitsklasse: -; Sonnenschutztyp: Movable; g-Wert: 0,51
 | H2 Ebene +1 | WA-LB | 1155Wa 0000004689 | yes | Codetext | m² | Trockenbauarbeiten | Wand | Außenwand 7-Schalig | WA-LB | 0 | A | 3.75 | 1155HWa0000004249 | NEW | no | yes | 0 | 0.9 | no | 32 | no | Codetext | AllplanAttributes - Sicherheitsklasse: -; Sonnenschutztyp: Movable; g-Wert: 0,51
 | H2 Ebene +1 | WA-DL | 1155Wa 0000004693 | yes | Codetext | m³ | Zimmer- und Holzbauarbeiten | Wand | Außenwand 7-Schalig | WA-DL | 0 | A | 3.75 | 1155HWa0000004249 | NEW | no | yes | 0 | 0.9 | no | 32 | no | Codetext | AllplanAttributes - Sicherheitsklasse: -; Sonnenschutztyp: Movable; g-Wert: 0,51; ash W_laufende Nr. Statik: 2 (W 2.0/ 2.1/ 2.2)
 | H2 Ebene +1 | WA-DL | 1155Wa 0000004697 | yes | Codetext | m³ | Zimmer- und Holzbauarbeiten | Wand | Außenwand 7-Schalig | WA-DL | 0 | A | 3.75 | 1155HWa0000004249 | NEW | no | yes | 0 | 0.9 | no | 32 | no | Codetext | AllplanAttributes - Sicherheitsklasse: -; Sonnenschutztyp: Movable; g-Wert: 0,51
 | H2 Ebene +1 | WA-LB | 1155Wa 0000004701 | yes | Codetext | m² | Trockenbauarbeiten | Wand | Außenwand 7-Schalig | WA-LB | 0 | A | 3.75 | 1155HWa0000004249 | NEW | no | yes | 0 | 0.9 | no | 32 | no | Codetext | AllplanAttributes - Sicherheitsklasse: -; Sonnenschutztyp: Movable; g-Wert: 0,51
 | H2 Ebene +1 | WA-KL | 1155Wa 0000004705 | yes | Codetext | m² | Zimmer- und Holzbauarbeiten | Wand | Außenwand 7-Schalig | WA-KL | 0 | A | 3.75 | 1155HWa0000004249 | NEW | no | yes | 0 | 0.9 | no | 32 | no | Codetext | AllplanAttributes - Sicherheitsklasse: -; Sonnenschutztyp: Movable; g-Wert: 0,51
 | H2 Ebene +1 | WA-TL | 1155Wa 0000004709 | yes | Codetext | m² | Zimmer- und Holzbauarbeiten | Wand | Außenwand 7-Schalig | WA-TL | 0 | A | 3.75 | 1155HWa0000004249 | NEW | no | yes | 0 | 0.9 | no | 32 | no | Codetext | AllplanAttributes - Sicherheitsklasse: -; Sonnenschutztyp: Movable; g-Wert: 0,51
 | H2 Ebene +1 | WA-HS | 1155Wa 0000004713 | yes | Codetext | m² | Zimmer- und Holzbauarbeiten | Wand | Außenwand 7-Schalig | WA-HS | 0 | A | 3.75 | 1155HWa0000004249 | NEW | no | yes | 0 | 0.9 | no | 32 | no | Codetext | AllplanAttributes - Sicherheitsklasse: -; Sonnenschutztyp: Movable; g-Wert: 0,51
 | H2 Ebene +1 | WA-LB | 1155Wa 0000004538 | yes | Codetext | m² | Trockenbauarbeiten | Wand | Außenwand 7-Schalig | WA-LB | 0 | A | 3.75 | 1155HWa0000004048 | NEW | no | yes | 0 | 0.9 | no | 32 | no | Codetext | AllplanAttributes - Sicherheitsklasse: -; Sonnenschutztyp: Movable; g-Wert: 0,51
 | H2 Ebene +1 | WA-DL | 1155Wa 0000004543 | yes | Codetext | m³ | Zimmer- und Holzbauarbeiten | Wand | Außenwand 7-Schalig | WA-DL | 0 | A | 3.75 | 1155HWa0000004048 | NEW | no | yes | 0 | 0.9 | no | 32 | no | Codetext | AllplanAttributes - Sicherheitsklasse: -; Sonnenschutztyp: Movable; g-Wert: 0,51; ash W_laufende Nr. Statik: 2 (W 2.0/ 2.1/ 2.2)
 | H2 Ebene +1 | WA-DL | 1155Wa 0000004548 | yes | Codetext | m³ | Zimmer- und Holzbauarbeiten | Wand | Außenwand 7-Schalig | WA-DL | 0 | A | 3.75 | 1155HWa0000004048 | NEW | no | yes | 0 | 0.9 | no | 32 | no | Codetext | AllplanAttributes - Sicherheitsklasse: -; Sonnenschutztyp: Movable; g-Wert: 0,51
 | H2 Ebene +1 | WA-LB | 1155Wa 0000004553 | yes | Codetext | m² | Trockenbauarbeiten | Wand | Außenwand 7-Schalig | WA-LB | 0 | A | 3.75 | 1155HWa0000004048 | NEW | no | yes | 0 | 0.9 | no | 32 | no | Codetext | AllplanAttributes - Sicherheitsklasse: -; Sonnenschutztyp: Movable; g-Wert: 0,51
 | H2 Ebene +1 | WA-KL | 1155Wa 0000004558 | yes | Codetext | m² | Zimmer- und Holzbauarbeiten | Wand | Außenwand 7-Schalig | WA-KL | 0 | A | 3.75 | 1155HWa0000004048 | NEW | no | yes | 0 | 0.9 | no | 32 | no | Codetext | AllplanAttributes - Sicherheitsklasse: -; Sonnenschutztyp: Movable; g-Wert: 0,51
 | H2 Ebene +1 | WA-TL | 1155Wa 0000004563 | yes | Codetext | m² | Zimmer- und Holzbauarbeiten | Wand | Außenwand 7-Schalig | WA-TL | 0 | A | 3.75 | 1155HWa0000004048 | NEW | no | yes | 0 | 0.9 | no | 32 | no | Codetext | AllplanAttributes - Sicherheitsklasse: -; Sonnenschutztyp: Movable; g-Wert: 0,51
 | H2 Ebene +1 | WA-HS | 1155Wa 0000004568 | yes | Codetext | m² | Zimmer- und Holzbauarbeiten | Wand | Außenwand 7-Schalig | WA-HS | 0 | A | 3.75 | 1155HWa0000004048 | NEW | no | yes | 0 | 0.9 | no | 32 | no | Codetext | AllplanAttributes - Sicherheitsklasse: -; Sonnenschutztyp: Movable; g-Wert: 0,51
2x Gipsfaserplatte | H2 Ebene +1 | WA-LB | 1155Wa 0000004481 | yes |  | m² | Trockenbauarbeiten | Wand | 2x Gipsfaserplatte | WA-LB |  |  | 3.75 | 1155HWa0000004472 | NEW | no | yes | 0 | 0.9 |  | 32 | AllplanAttributes - Sicherheitsklasse: -; Sonnenschutztyp: Movable; g-Wert: 0,51
Holzständer + Zwischendämmung | H2 Ebene +1 | WA-DL | 1155Wa 0000004483 | yes |  | m³ | Zimmer- und Holzbauarbeiten | Wand | Holzständer + Zwischendämmung | WA-DL |  |  | 3.75 | 1155HWa0000004472 | NEW | no | yes | 0 | 0.9 |  | 32 | AllplanAttributes - Sicherheitsklasse: -; Sonnenschutztyp: Movable; g-Wert: 0,51; ash W_laufende Nr. Statik: 2 (W 2.0/ 2.1/ 2.2)
Staffel + Zwischendämmung | H2 Ebene +1 | WA-DL | 1155Wa 0000004485 | yes |  | m³ | Zimmer- und Holzbauarbeiten | Wand | Staffel + Zwischendämmung | WA-DL |  |  | 3.75 | 1155HWa0000004472 | NEW | no | yes | 0 | 0.9 |  | 32 | AllplanAttributes - Sicherheitsklasse: -; Sonnenschutztyp: Movable; g-Wert: 0,51
 | H2 Ebene +1 | WA-LB | 1155Wa 0000004487 | yes | Codetext | m² | Trockenbauarbeiten | Wand | Außenwand 7-Schalig | WA-LB | 0 | A | 3.75 | 1155HWa0000004472 | NEW | no | yes | 0 | 0.9 | no | 32 | no | Codetext | AllplanAttributes - Sicherheitsklasse: -; Sonnenschutztyp: Movable; g-Wert: 0,51
Konterlattung | H2 Ebene +1 | WA-KL | 1155Wa 0000004489 | yes |  | m² | Zimmer- und Holzbauarbeiten | Wand | Konterlattung | WA-KL |  |  | 3.75 | 1155HWa0000004472 | NEW | no | yes | 0 | 0.9 |  | 32 | AllplanAttributes - Sicherheitsklasse: -; Sonnenschutztyp: Movable; g-Wert: 0,51
Traglattung | H2 Ebene +1 | WA-TL | 1155Wa 0000004491 | yes |  | m² | Zimmer- und Holzbauarbeiten | Wand | Traglattung | WA-TL |  |  | 3.75 | 1155HWa0000004472 | NEW | no | yes | 0 | 0.9 |  | 32 | AllplanAttributes - Sicherheitsklasse: -; Sonnenschutztyp: Movable; g-Wert: 0,51
Holzschindel | H2 Ebene +1 | WA-HS | 1155Wa 0000004493 | yes |  | m² | Zimmer- und Holzbauarbeiten | Wand | Holzschindel | WA-HS |  |  | 3.75 | 1155HWa0000004472 | NEW | no | yes | 0 | 0.9 |  | 32 | AllplanAttributes - Sicherheitsklasse: -; Sonnenschutztyp: Movable; g-Wert: 0,51
 | H2 Ebene +1 | WA-LB | 1155Wa 0000004893 | yes | Codetext | m² | Trockenbauarbeiten | Wand | Außenwand 7-Schalig | WA-LB | 0 | A | 3.75 | 1155HWa0000004161 | NEW | no | yes | 0 | 0.9 | no | 32 | no | Codetext | AllplanAttributes - Sicherheitsklasse: -; Sonnenschutztyp: Movable; g-Wert: 0,51
 | H2 Ebene +1 | WA-DL | 1155Wa 0000004889 | yes | Codetext | m³ | Zimmer- und Holzbauarbeiten | Wand | Außenwand 7-Schalig | WA-DL | 0 | A | 3.75 | 1155HWa0000004161 | NEW | no | yes | 0 | 0.9 | no | 32 | no | Codetext | AllplanAttributes - Sicherheitsklasse: -; Sonnenschutztyp: Movable; g-Wert: 0,51; ash W_laufende Nr. Statik: 2 (W 2.0/ 2.1/ 2.2)
 | H2 Ebene +1 | WA-DL | 1155Wa 0000004885 | yes | Codetext | m³ | Zimmer- und Holzbauarbeiten | Wand | Außenwand 7-Schalig | WA-DL | 0 | A | 3.75 | 1155HWa0000004161 | NEW | no | yes | 0 | 0.9 | no | 32 | no | Codetext | AllplanAttributes - Sicherheitsklasse: -; Sonnenschutztyp: Movable; g-Wert: 0,51
 | H2 Ebene +1 | WA-LB | 1155Wa 0000004881 | yes | Codetext | m² | Trockenbauarbeiten | Wand | Außenwand 7-Schalig | WA-LB | 0 | A | 3.75 | 1155HWa0000004161 | NEW | no | yes | 0 | 0.9 | no | 32 | no | Codetext | AllplanAttributes - Sicherheitsklasse: -; Sonnenschutztyp: Movable; g-Wert: 0,51
 | H2 Ebene +1 | WA-KL | 1155Wa 0000004877 | yes | Codetext | m² | Zimmer- und Holzbauarbeiten | Wand | Außenwand 7-Schalig | WA-KL | 0 | A | 3.75 | 1155HWa0000004161 | NEW | no | yes | 0 | 0.9 | no | 32 | no | Codetext | AllplanAttributes - Sicherheitsklasse: -; Sonnenschutztyp: Movable; g-Wert: 0,51
 | H2 Ebene +1 | WA-TL | 1155Wa 0000004873 | yes | Codetext | m² | Zimmer- und Holzbauarbeiten | Wand | Außenwand 7-Schalig | WA-TL | 0 | A | 3.75 | 1155HWa0000004161 | NEW | no | yes | 0 | 0.9 | no | 32 | no | Codetext | AllplanAttributes - Sicherheitsklasse: -; Sonnenschutztyp: Movable; g-Wert: 0,51
 | H2 Ebene +1 | WA-HS | 1155Wa 0000004869 | yes | Codetext | m² | Zimmer- und Holzbauarbeiten | Wand | Außenwand 7-Schalig | WA-HS | 0 | A | 3.75 | 1155HWa0000004161 | NEW | no | yes | 0 | 0.9 | no | 32 | no | Codetext | AllplanAttributes - Sicherheitsklasse: -; Sonnenschutztyp: Movable; g-Wert: 0,51
2x Gipsfaserplatte | H2 Ebene +1 | WA-LB | 1155Wa 0000004830 | yes |  | m² | Trockenbauarbeiten | Wand | 2x Gipsfaserplatte | WA-LB |  |  | 3.75 | 1155HWa0000004816 | NEW | no | yes | 0 | 0.9 |  | 32 | AllplanAttributes - Sicherheitsklasse: -; Sonnenschutztyp: Movable; g-Wert: 0,51
Holzständer + Zwischendämmung | H2 Ebene +1 | WA-DL | 1155Wa 0000004828 | yes |  | m³ | Zimmer- und Holzbauarbeiten | Wand | Holzständer + Zwischendämmung | WA-DL |  |  | 3.75 | 1155HWa0000004816 | NEW | no | yes | 0 | 0.9 |  | 32 | AllplanAttributes - Sicherheitsklasse: -; Sonnenschutztyp: Movable; g-Wert: 0,51; ash W_laufende Nr. Statik: 2 (W 2.0/ 2.1/ 2.2)
Staffel + Zwischendämmung | H2 Ebene +1 | WA-DL | 1155Wa 0000004826 | yes |  | m³ | Zimmer- und Holzbauarbeiten | Wand | Staffel + Zwischendämmung | WA-DL |  |  | 3.75 | 1155HWa0000004816 | NEW | no | yes | 0 | 0.9 |  | 32 | AllplanAttributes - Sicherheitsklasse: -; Sonnenschutztyp: Movable; g-Wert: 0,51
 | H2 Ebene +1 | WA-LB | 1155Wa 0000004824 | yes | Codetext | m² | Trockenbauarbeiten | Wand | Außenwand 7-Schalig | WA-LB | 0 | A | 3.75 | 1155HWa0000004816 | NEW | no | yes | 0 | 0.9 | no | 32 | no | Codetext | AllplanAttributes - Sicherheitsklasse: -; Sonnenschutztyp: Movable; g-Wert: 0,51
Konterlattung | H2 Ebene +1 | WA-KL | 1155Wa 0000004822 | yes |  | m² | Zimmer- und Holzbauarbeiten | Wand | Konterlattung | WA-KL |  |  | 3.75 | 1155HWa0000004816 | NEW | no | yes | 0 | 0.9 |  | 32 | AllplanAttributes - Sicherheitsklasse: -; Sonnenschutztyp: Movable; g-Wert: 0,51
Traglattung | H2 Ebene +1 | WA-TL | 1155Wa 0000004820 | yes |  | m² | Zimmer- und Holzbauarbeiten | Wand | Traglattung | WA-TL |  |  | 3.75 | 1155HWa0000004816 | NEW | no | yes | 0 | 0.9 |  | 32 | AllplanAttributes - Sicherheitsklasse: -; Sonnenschutztyp: Movable; g-Wert: 0,51
Holzschindel | H2 Ebene +1 | WA-HS | 1155Wa 0000004818 | yes |  | m² | Zimmer- und Holzbauarbeiten | Wand | Holzschindel | WA-HS |  |  | 3.75 | 1155HWa0000004816 | NEW | no | yes | 0 | 0.9 |  | 32 | AllplanAttributes - Sicherheitsklasse: -; Sonnenschutztyp: Movable; g-Wert: 0,51
 | H2 Ebene +1 | WA-LB | 1155Wa 0000004509 | yes | Codetext | m² | Trockenbauarbeiten | Wand | Außenwand 7-Schalig | WA-LB | 0 | A | 3.75 | 1155HWa0000004474 | NEW | no | yes | 0 | 0.9 | no | 32 | no | Codetext | AllplanAttributes - Sicherheitsklasse: -; Sonnenschutztyp: Movable; g-Wert: 0,51
 | H2 Ebene +1 | WA-DL | 1155Wa 0000004511 | yes | Codetext | m³ | Zimmer- und Holzbauarbeiten | Wand | Außenwand 7-Schalig | WA-DL | 0 | A | 3.75 | 1155HWa0000004474 | NEW | no | yes | 0 | 0.9 | no | 32 | no | Codetext | AllplanAttributes - ash D_Detailverweis: DT D; ash D_Plannummer: D1851; Sicherheitsklasse: -; Sonnenschutztyp: Movable; g-Wert: 0,51; ash W_laufende Nr. Statik: 2 (W 2.0/ 2.1/ 2.2)
 | H2 Ebene +1 | WA-DL | 1155Wa 0000004513 | yes | Codetext | m³ | Zimmer- und Holzbauarbeiten | Wand | Außenwand 7-Schalig | WA-DL | 0 | A | 3.75 | 1155HWa0000004474 | NEW | no | yes | 0 | 0.9 | no | 32 | no | Codetext | AllplanAttributes - Sicherheitsklasse: -; Sonnenschutztyp: Movable; g-Wert: 0,51
 | H2 Ebene +1 | WA-LB | 1155Wa 0000004515 | yes | Codetext | m² | Trockenbauarbeiten | Wand | Außenwand 7-Schalig | WA-LB | 0 | A | 3.75 | 1155HWa0000004474 | NEW | no | yes | 0 | 0.9 | no | 32 | no | Codetext | AllplanAttributes - Sicherheitsklasse: -; Sonnenschutztyp: Movable; g-Wert: 0,51
 | H2 Ebene +1 | WA-KL | 1155Wa 0000004517 | yes | Codetext | m² | Zimmer- und Holzbauarbeiten | Wand | Außenwand 7-Schalig | WA-KL | 0 | A | 3.75 | 1155HWa0000004474 | NEW | no | yes | 0 | 0.9 | no | 32 | no | Codetext | AllplanAttributes - Sicherheitsklasse: -; Sonnenschutztyp: Movable; g-Wert: 0,51
 | H2 Ebene +1 | WA-TL | 1155Wa 0000004519 | yes | Codetext | m² | Zimmer- und Holzbauarbeiten | Wand | Außenwand 7-Schalig | WA-TL | 0 | A | 3.75 | 1155HWa0000004474 | NEW | no | yes | 0 | 0.9 | no | 32 | no | Codetext | AllplanAttributes - Sicherheitsklasse: -; Sonnenschutztyp: Movable; g-Wert: 0,51
 | H2 Ebene +1 | WA-HS | 1155Wa 0000004521 | yes | Codetext | m² | Zimmer- und Holzbauarbeiten | Wand | Außenwand 7-Schalig | WA-HS | 0 | A | 3.75 | 1155HWa0000004474 | NEW | no | yes | 0 | 0.9 | no | 32 | no | Codetext | AllplanAttributes - Sicherheitsklasse: -; Sonnenschutztyp: Movable; g-Wert: 0,51
 | H2 Ebene +1 | WA-LB | 1155Wa 0000005133 | yes | Codetext | m² | Trockenbauarbeiten | Wand | Außenwand 7-Schalig | WA-LB | 0 | A | 3.75 | 1155HWa0000003250 | NEW | no | yes | 0 | 0.9 | no | 32 | no | Codetext | AllplanAttributes - Sicherheitsklasse: -; Sonnenschutztyp: Movable; g-Wert: 0,51
 | H2 Ebene +1 | WA-DL | 1155Wa 0000005124 | yes | Codetext | m³ | Zimmer- und Holzbauarbeiten | Wand | Außenwand 7-Schalig | WA-DL | 0 | A | 3.75 | 1155HWa0000003250 | NEW | no | yes | 0 | 0.9 | no | 32 | no | Codetext | AllplanAttributes - ash D_Detailverweis: DT D; ash D_Plannummer: D1851; Sicherheitsklasse: -; Sonnenschutztyp: Movable; g-Wert: 0,51; ash W_laufende Nr. Statik: 2 (W 2.0/ 2.1/ 2.2)
 | H2 Ebene +1 | WA-DL | 1155Wa 0000005115 | yes | Codetext | m³ | Zimmer- und Holzbauarbeiten | Wand | Außenwand 7-Schalig | WA-DL | 0 | A | 3.75 | 1155HWa0000003250 | NEW | no | yes | 0 | 0.9 | no | 32 | no | Codetext | AllplanAttributes - Sicherheitsklasse: -; Sonnenschutztyp: Movable; g-Wert: 0,51
 | H2 Ebene +1 | WA-LB | 1155Wa 0000005106 | yes | Codetext | m² | Trockenbauarbeiten | Wand | Außenwand 7-Schalig | WA-LB | 0 | A | 3.75 | 1155HWa0000003250 | NEW | no | yes | 0 | 0.9 | no | 32 | no | Codetext | AllplanAttributes - Sicherheitsklasse: -; Sonnenschutztyp: Movable; g-Wert: 0,51
 | H2 Ebene +1 | WA-KL | 1155Wa 0000005097 | yes | Codetext | m² | Zimmer- und Holzbauarbeiten | Wand | Außenwand 7-Schalig | WA-KL | 0 | A | 3.75 | 1155HWa0000003250 | NEW | no | yes | 0 | 0.9 | no | 32 | no | Codetext | AllplanAttributes - Sicherheitsklasse: -; Sonnenschutztyp: Movable; g-Wert: 0,51
 | H2 Ebene +1 | WA-TL | 1155Wa 0000005088 | yes | Codetext | m² | Zimmer- und Holzbauarbeiten | Wand | Außenwand 7-Schalig | WA-TL | 0 | A | 3.75 | 1155HWa0000003250 | NEW | no | yes | 0 | 0.9 | no | 32 | no | Codetext | AllplanAttributes - Sicherheitsklasse: -; Sonnenschutztyp: Movable; g-Wert: 0,51
 | H2 Ebene +1 | WA-HS | 1155Wa 0000005079 | yes | Codetext | m² | Zimmer- und Holzbauarbeiten | Wand | Außenwand 7-Schalig | WA-HS | 0 | A | 3.75 | 1155HWa0000003250 | NEW | no | yes | 0 | 0.9 | no | 32 | no | Codetext | AllplanAttributes - Sicherheitsklasse: -; Sonnenschutztyp: Movable; g-Wert: 0,51
 | H2 Ebene +1 | WA-STB | 1155Wa 0000002335 | yes | Codetext | m² | Zimmer- und Holzbauarbeiten | Wand | Außenwand 2-Schalig | WA-STB | 0 | A | 3.75 | 1155HWa0000002256 | NEW | no | yes | 0 | 0.9 | no | 32 | no | Codetext | AllplanAttributes - Sicherheitsklasse: -; Sonnenschutztyp: Movable; g-Wert: 0,51
 | H2 Ebene +1 | WA-DL | 1155Wa 0000002341 | yes | Codetext | m³ | Zimmer- und Holzbauarbeiten | Wand | Außenwand 2-Schalig | WA-DL | 0 | A | 3.75 | 1155HWa0000002256 | NEW | no | yes | 0 | 0.9 | no | 32 | no | Codetext | AllplanAttributes - Sicherheitsklasse: -; Sonnenschutztyp: Movable; g-Wert: 0,51
 | H2 Ebene +1 | WA-LB | 1155Wa 0000002347 | yes | Codetext | m² | Trockenbauarbeiten | Wand | Außenwand 2-Schalig | WA-LB | 0 | A | 3.75 | 1155HWa0000002256 | NEW | no | yes | 0 | 0.9 | no | 32 | no | Codetext | AllplanAttributes - Sicherheitsklasse: -; Sonnenschutztyp: Movable; g-Wert: 0,51
 | H2 Ebene +1 | WA-KL | 1155Wa 0000002353 | yes | Codetext | m² | Zimmer- und Holzbauarbeiten | Wand | Außenwand 2-Schalig | WA-KL | 0 | A | 3.75 | 1155HWa0000002256 | NEW | no | yes | 0 | 0.9 | no | 32 | no | Codetext | AllplanAttributes - Sicherheitsklasse: -; Sonnenschutztyp: Movable; g-Wert: 0,51
 | H2 Ebene +1 | WA-TL | 1155Wa 0000002359 | yes | Codetext | m² | Zimmer- und Holzbauarbeiten | Wand | Außenwand 2-Schalig | WA-TL | 0 | A | 3.75 | 1155HWa0000002256 | NEW | no | yes | 0 | 0.9 | no | 32 | no | Codetext | AllplanAttributes - Sicherheitsklasse: -; Sonnenschutztyp: Movable; g-Wert: 0,51
 | H2 Ebene +1 | WA-HS | 1155Wa 0000081159 | yes | Codetext | m² | Zimmer- und Holzbauarbeiten | Wand | Außenwand 2-Schalig | WA-HS | 0 | A | 3.75 | 1155HWa0000002256 | NEW | no | yes | 0 | 0.9 | no | 32 | no | Codetext | AllplanAttributes - Sicherheitsklasse: -; Sonnenschutztyp: Movable; g-Wert: 0,51
 | H2 Ebene +1 | WA-STB | 1155Wa 0000081025 | yes | Codetext | m² | Zimmer- und Holzbauarbeiten | Wand | Außenwand 2-Schalig | WA-STB | 0 | A | 3.75 | 1155HWa0000081024 | NEW | no | yes | 0 | 0.9 | no | 32 | no | Codetext | AllplanAttributes - Sicherheitsklasse: -; Sonnenschutztyp: Movable; g-Wert: 0,51
 | H2 Ebene +1 | WA-DL | 1155Wa 0000081026 | yes | Codetext | m³ | Zimmer- und Holzbauarbeiten | Wand | Außenwand 2-Schalig | WA-DL | 0 | A | 3.75 | 1155HWa0000081024 | NEW | no | yes | 0 | 0.9 | no | 32 | no | Codetext | AllplanAttributes - Sicherheitsklasse: -; Sonnenschutztyp: Movable; g-Wert: 0,51
 | H2 Ebene +1 | WA-LB | 1155Wa 0000081027 | yes | Codetext | m² | Trockenbauarbeiten | Wand | Außenwand 2-Schalig | WA-LB | 0 | A | 3.75 | 1155HWa0000081024 | NEW | no | yes | 0 | 0.9 | no | 32 | no | Codetext | AllplanAttributes - Sicherheitsklasse: -; Sonnenschutztyp: Movable; g-Wert: 0,51
 | H2 Ebene +1 | WA-KL | 1155Wa 0000081028 | yes | Codetext | m² | Zimmer- und Holzbauarbeiten | Wand | Außenwand 2-Schalig | WA-KL | 0 | A | 3.75 | 1155HWa0000081024 | NEW | no | yes | 0 | 0.9 | no | 32 | no | Codetext | AllplanAttributes - Sicherheitsklasse: -; Sonnenschutztyp: Movable; g-Wert: 0,51
 | H2 Ebene +1 | WA-TL | 1155Wa 0000081029 | yes | Codetext | m² | Zimmer- und Holzbauarbeiten | Wand | Außenwand 2-Schalig | WA-TL | 0 | A | 3.75 | 1155HWa0000081024 | NEW | no | yes | 0 | 0.9 | no | 32 | no | Codetext | AllplanAttributes - Sicherheitsklasse: -; Sonnenschutztyp: Movable; g-Wert: 0,51
 | H2 Ebene +1 | WA-HS | 1155Wa 0000081681 | yes | Codetext | m² | Zimmer- und Holzbauarbeiten | Wand | Außenwand 2-Schalig | WA-HS | 0 | A | 3.75 | 1155HWa0000081024 | NEW | no | yes | 0 | 0.9 | no | 32 | no | Codetext | AllplanAttributes - Sicherheitsklasse: -; Sonnenschutztyp: Movable; g-Wert: 0,51
 | H2 Ebene +1 | WA-STB | 1155Wa 0000002369 | yes | Codetext | m² | Zimmer- und Holzbauarbeiten | Wand | Außenwand 2-Schalig | WA-STB | 0 | A | 3.75 | 1155HWa0000002254 | NEW | no | yes | 0 | 0.9 | no | 32 | no | Codetext | AllplanAttributes - Sicherheitsklasse: -; Sonnenschutztyp: Movable; g-Wert: 0,51
 | H2 Ebene +1 | WA-DL | 1155Wa 0000002399 | yes | Codetext | m³ | Zimmer- und Holzbauarbeiten | Wand | Außenwand 2-Schalig | WA-DL | 0 | A | 3.75 | 1155HWa0000002254 | NEW | no | yes | 0 | 0.9 | no | 32 | no | Codetext | AllplanAttributes - Sicherheitsklasse: -; Sonnenschutztyp: Movable; g-Wert: 0,51
 | H2 Ebene +1 | WA-LB | 1155Wa 0000002401 | yes | Codetext | m² | Trockenbauarbeiten | Wand | Außenwand 2-Schalig | WA-LB | 0 | A | 3.75 | 1155HWa0000002254 | NEW | no | yes | 0 | 0.9 | no | 32 | no | Codetext | AllplanAttributes - Sicherheitsklasse: -; Sonnenschutztyp: Movable; g-Wert: 0,51
 | H2 Ebene +1 | WA-KL | 1155Wa 0000002403 | yes | Codetext | m² | Zimmer- und Holzbauarbeiten | Wand | Außenwand 2-Schalig | WA-KL | 0 | A | 3.75 | 1155HWa0000002254 | NEW | no | yes | 0 | 0.9 | no | 32 | no | Codetext | AllplanAttributes - Sicherheitsklasse: -; Sonnenschutztyp: Movable; g-Wert: 0,51
 | H2 Ebene +1 | WA-TL | 1155Wa 0000002405 | yes | Codetext | m² | Zimmer- und Holzbauarbeiten | Wand | Außenwand 2-Schalig | WA-TL | 0 | A | 3.75 | 1155HWa0000002254 | NEW | no | yes | 0 | 0.9 | no | 32 | no | Codetext | AllplanAttributes - Sicherheitsklasse: -; Sonnenschutztyp: Movable; g-Wert: 0,51
 | H2 Ebene +1 | WA-HS | 1155Wa 0000081591 | yes | Codetext | m² | Zimmer- und Holzbauarbeiten | Wand | Außenwand 2-Schalig | WA-HS | 0 | A | 3.75 | 1155HWa0000002254 | NEW | no | yes | 0 | 0.9 | no | 32 | no | Codetext | AllplanAttributes - Sicherheitsklasse: -; Sonnenschutztyp: Movable; g-Wert: 0,51
 | H2 Ebene +1 | WA-STB | 1155Wa 0000081745 | yes | Codetext | m² | Zimmer- und Holzbauarbeiten | Wand | Außenwand 2-Schalig | WA-STB | 0 | A | 3.75 | 1155HWa0000081744 | NEW | no | yes | 0 | 0.9 | no | 32 | no | Codetext | AllplanAttributes - Sicherheitsklasse: -; Sonnenschutztyp: Movable; g-Wert: 0,51
 | H2 Ebene +1 | WA-DL | 1155Wa 0000081746 | yes | Codetext | m³ | Zimmer- und Holzbauarbeiten | Wand | Außenwand 2-Schalig | WA-DL | 0 | A | 3.75 | 1155HWa0000081744 | NEW | no | yes | 0 | 0.9 | no | 32 | no | Codetext | AllplanAttributes - Sicherheitsklasse: -; Sonnenschutztyp: Movable; g-Wert: 0,51
 | H2 Ebene +1 | WA-LB | 1155Wa 0000081747 | yes | Codetext | m² | Trockenbauarbeiten | Wand | Außenwand 2-Schalig | WA-LB | 0 | A | 3.75 | 1155HWa0000081744 | NEW | no | yes | 0 | 0.9 | no | 32 | no | Codetext | AllplanAttributes - Sicherheitsklasse: -; Sonnenschutztyp: Movable; g-Wert: 0,51
 | H2 Ebene +1 | WA-KL | 1155Wa 0000081748 | yes | Codetext | m² | Zimmer- und Holzbauarbeiten | Wand | Außenwand 2-Schalig | WA-KL | 0 | A | 3.75 | 1155HWa0000081744 | NEW | no | yes | 0 | 0.9 | no | 32 | no | Codetext | AllplanAttributes - Sicherheitsklasse: -; Sonnenschutztyp: Movable; g-Wert: 0,51
 | H2 Ebene +1 | WA-TL | 1155Wa 0000081749 | yes | Codetext | m² | Zimmer- und Holzbauarbeiten | Wand | Außenwand 2-Schalig | WA-TL | 0 | A | 3.75 | 1155HWa0000081744 | NEW | no | yes | 0 | 0.9 | no | 32 | no | Codetext | AllplanAttributes - Sicherheitsklasse: -; Sonnenschutztyp: Movable; g-Wert: 0,51
 | H2 Ebene +1 | WA-HS | 1155Wa 0000081750 | yes | Codetext | m² | Zimmer- und Holzbauarbeiten | Wand | Außenwand 2-Schalig | WA-HS | 0 | A | 3.75 | 1155HWa0000081744 | NEW | no | yes | 0 | 0.9 | no | 32 | no | Codetext | AllplanAttributes - Sicherheitsklasse: -; Sonnenschutztyp: Movable; g-Wert: 0,51
 | H2 Ebene +1 | WA-STB | 1155Wa 0000002371 | yes | Codetext | m² | Zimmer- und Holzbauarbeiten | Wand | Außenwand 2-Schalig | WA-STB | 0 | A | 3.75 | 1155HWa0000002217 | NEW | no | yes | 0 | 0.9 | no | 32 | no | Codetext | AllplanAttributes - Sicherheitsklasse: -; Sonnenschutztyp: Movable; g-Wert: 0,51
 | H2 Ebene +1 | WA-DL | 1155Wa 0000002367 | yes | Codetext | m³ | Zimmer- und Holzbauarbeiten | Wand | Außenwand 2-Schalig | WA-DL | 0 | A | 3.75 | 1155HWa0000002217 | NEW | no | yes | 0 | 0.9 | no | 32 | no | Codetext | AllplanAttributes - Sicherheitsklasse: -; Sonnenschutztyp: Movable; g-Wert: 0,51
 | H2 Ebene +1 | WA-LB | 1155Wa 0000002365 | yes | Codetext | m² | Trockenbauarbeiten | Wand | Außenwand 2-Schalig | WA-LB | 0 | A | 3.75 | 1155HWa0000002217 | NEW | no | yes | 0 | 0.9 | no | 32 | no | Codetext | AllplanAttributes - Sicherheitsklasse: -; Sonnenschutztyp: Movable; g-Wert: 0,51
 | H2 Ebene +1 | WA-KL | 1155Wa 0000002363 | yes | Codetext | m² | Zimmer- und Holzbauarbeiten | Wand | Außenwand 2-Schalig | WA-KL | 0 | A | 3.75 | 1155HWa0000002217 | NEW | no | yes | 0 | 0.9 | no | 32 | no | Codetext | AllplanAttributes - Sicherheitsklasse: -; Sonnenschutztyp: Movable; g-Wert: 0,51
 | H2 Ebene +1 | WA-TL | 1155Wa 0000002361 | yes | Codetext | m² | Zimmer- und Holzbauarbeiten | Wand | Außenwand 2-Schalig | WA-TL | 0 | A | 3.75 | 1155HWa0000002217 | NEW | no | yes | 0 | 0.9 | no | 32 | no | Codetext | AllplanAttributes - Sicherheitsklasse: -; Sonnenschutztyp: Movable; g-Wert: 0,51
 | H2 Ebene +1 | WA-HS | 1155Wa 0000081058 | yes | Codetext | m² | Zimmer- und Holzbauarbeiten | Wand | Außenwand 2-Schalig | WA-HS | 0 | A | 3.75 | 1155HWa0000002217 | NEW | no | yes | 0 | 0.9 | no | 32 | no | Codetext | AllplanAttributes - Sicherheitsklasse: -; Sonnenschutztyp: Movable; g-Wert: 0,51
 | H2 Ebene +1 | WA-STB | 1155Wa 0000002989 | yes | Codetext | m² | Zimmer- und Holzbauarbeiten | Wand | Außenwand 2-Schalig | WA-STB | 0 | A | 3.75 | 1155HWa0000002929 | NEW | no | yes | 0 | 0.9 | no | 32 | no | Codetext | AllplanAttributes - Sicherheitsklasse: -; Sonnenschutztyp: Movable; g-Wert: 0,51
 | H2 Ebene +1 | WA-DL | 1155Wa 0000002987 | yes | Codetext | m³ | Zimmer- und Holzbauarbeiten | Wand | Außenwand 2-Schalig | WA-DL | 0 | A | 3.75 | 1155HWa0000002929 | NEW | no | yes | 0 | 0.9 | no | 32 | no | Codetext | AllplanAttributes - Sicherheitsklasse: -; Sonnenschutztyp: Movable; g-Wert: 0,51
 | H2 Ebene +1 | WA-LB | 1155Wa 0000002985 | yes | Codetext | m² | Trockenbauarbeiten | Wand | Außenwand 2-Schalig | WA-LB | 0 | A | 3.75 | 1155HWa0000002929 | NEW | no | yes | 0 | 0.9 | no | 32 | no | Codetext | AllplanAttributes - Sicherheitsklasse: -; Sonnenschutztyp: Movable; g-Wert: 0,51
 | H2 Ebene +1 | WA-KL | 1155Wa 0000002983 | yes | Codetext | m² | Zimmer- und Holzbauarbeiten | Wand | Außenwand 2-Schalig | WA-KL | 0 | A | 3.75 | 1155HWa0000002929 | NEW | no | yes | 0 | 0.9 | no | 32 | no | Codetext | AllplanAttributes - Sicherheitsklasse: -; Sonnenschutztyp: Movable; g-Wert: 0,51
 | H2 Ebene +1 | WA-TL | 1155Wa 0000002981 | yes | Codetext | m² | Zimmer- und Holzbauarbeiten | Wand | Außenwand 2-Schalig | WA-TL | 0 | A | 3.75 | 1155HWa0000002929 | NEW | no | yes | 0 | 0.9 | no | 32 | no | Codetext | AllplanAttributes - Sicherheitsklasse: -; Sonnenschutztyp: Movable; g-Wert: 0,51
 | H2 Ebene +1 | WA-HS | 1155Wa 0000081999 | yes | Codetext | m² | Zimmer- und Holzbauarbeiten | Wand | Außenwand 2-Schalig | WA-HS | 0 | A | 3.75 | 1155HWa0000002929 | NEW | no | yes | 0 | 0.9 | no | 32 | no | Codetext | AllplanAttributes - Sicherheitsklasse: -; Sonnenschutztyp: Movable; g-Wert: 0,51
 | H2 Ebene +1 | WA-STB | 1155Wa 0000003016 | yes | Codetext | m² | Zimmer- und Holzbauarbeiten | Wand | Außenwand 2-Schalig | WA-STB | 0 | A | 3.75 | 1155HWa0000002943 | NEW | no | yes | 0 | 0.9 | no | 32 | no | Codetext | AllplanAttributes - Sicherheitsklasse: -; Sonnenschutztyp: Movable; g-Wert: 0,51
 | H2 Ebene +1 | WA-DL | 1155Wa 0000002967 | yes | Codetext | m³ | Zimmer- und Holzbauarbeiten | Wand | Außenwand 2-Schalig | WA-DL | 0 | A | 3.75 | 1155HWa0000002943 | NEW | no | yes | 0 | 0.9 | no | 32 | no | Codetext | AllplanAttributes - Sicherheitsklasse: -; Sonnenschutztyp: Movable; g-Wert: 0,51
 | H2 Ebene +1 | WA-LB | 1155Wa 0000002971 | yes | Codetext | m² | Trockenbauarbeiten | Wand | Außenwand 2-Schalig | WA-LB | 0 | A | 3.75 | 1155HWa0000002943 | NEW | no | yes | 0 | 0.9 | no | 32 | no | Codetext | AllplanAttributes - Sicherheitsklasse: -; Sonnenschutztyp: Movable; g-Wert: 0,51
 | H2 Ebene +1 | WA-KL | 1155Wa 0000002975 | yes | Codetext | m² | Zimmer- und Holzbauarbeiten | Wand | Außenwand 2-Schalig | WA-KL | 0 | A | 3.75 | 1155HWa0000002943 | NEW | no | yes | 0 | 0.9 | no | 32 | no | Codetext | AllplanAttributes - Sicherheitsklasse: -; Sonnenschutztyp: Movable; g-Wert: 0,51
 | H2 Ebene +1 | WA-TL | 1155Wa 0000002979 | yes | Codetext | m² | Zimmer- und Holzbauarbeiten | Wand | Außenwand 2-Schalig | WA-TL | 0 | A | 3.75 | 1155HWa0000002943 | NEW | no | yes | 0 | 0.9 | no | 32 | no | Codetext | AllplanAttributes - Sicherheitsklasse: -; Sonnenschutztyp: Movable; g-Wert: 0,51
 | H2 Ebene +1 | WA-HS | 1155Wa 0000082689 | yes | Codetext | m² | Zimmer- und Holzbauarbeiten | Wand | Außenwand 2-Schalig | WA-HS | 0 | A | 3.75 | 1155HWa0000002943 | NEW | no | yes | 0 | 0.9 | no | 32 | no | Codetext | AllplanAttributes - Sicherheitsklasse: -; Sonnenschutztyp: Movable; g-Wert: 0,51
 | H2 Ebene +1 | WA-STB | 1155Wa 0000083587 | yes | Codetext | m² | Zimmer- und Holzbauarbeiten | Wand | Außenwand 2-Schalig | WA-STB | 0 | A | 3.75 | 1155HWa0000083586 | NEW | no | yes | 0 | 0.9 | no | 32 | no | Codetext | AllplanAttributes - Sicherheitsklasse: -; Sonnenschutztyp: Movable; g-Wert: 0,51
 | H2 Ebene +1 | WA-DL | 1155Wa 0000083588 | yes | Codetext | m³ | Zimmer- und Holzbauarbeiten | Wand | Außenwand 2-Schalig | WA-DL | 0 | A | 3.75 | 1155HWa0000083586 | NEW | no | yes | 0 | 0.9 | no | 32 | no | Codetext | AllplanAttributes - Sicherheitsklasse: -; Sonnenschutztyp: Movable; g-Wert: 0,51
 | H2 Ebene +1 | WA-LB | 1155Wa 0000083589 | yes | Codetext | m² | Trockenbauarbeiten | Wand | Außenwand 2-Schalig | WA-LB | 0 | A | 3.75 | 1155HWa0000083586 | NEW | no | yes | 0 | 0.9 | no | 32 | no | Codetext | AllplanAttributes - Sicherheitsklasse: -; Sonnenschutztyp: Movable; g-Wert: 0,51
 | H2 Ebene +1 | WA-KL | 1155Wa 0000083590 | yes | Codetext | m² | Zimmer- und Holzbauarbeiten | Wand | Außenwand 2-Schalig | WA-KL | 0 | A | 3.75 | 1155HWa0000083586 | NEW | no | yes | 0 | 0.9 | no | 32 | no | Codetext | AllplanAttributes - Sicherheitsklasse: -; Sonnenschutztyp: Movable; g-Wert: 0,51
 | H2 Ebene +1 | WA-TL | 1155Wa 0000083591 | yes | Codetext | m² | Zimmer- und Holzbauarbeiten | Wand | Außenwand 2-Schalig | WA-TL | 0 | A | 3.75 | 1155HWa0000083586 | NEW | no | yes | 0 | 0.9 | no | 32 | no | Codetext | AllplanAttributes - Sicherheitsklasse: -; Sonnenschutztyp: Movable; g-Wert: 0,51
 | H2 Ebene +1 | WA-HS | 1155Wa 0000083592 | yes | Codetext | m² | Zimmer- und Holzbauarbeiten | Wand | Außenwand 2-Schalig | WA-HS | 0 | A | 3.75 | 1155HWa0000083586 | NEW | no | yes | 0 | 0.9 | no | 32 | no | Codetext | AllplanAttributes - Sicherheitsklasse: -; Sonnenschutztyp: Movable; g-Wert: 0,51
 | H2 Ebene +1 | WA-STB | 1155Wa 0000121099 | yes | Codetext | m² | Zimmer- und Holzbauarbeiten | Wand | Außenwand 2-Schalig | WA-STB | 0 | A | 3.75 | 1155HWa0000121097 | NEW | no | yes | 0 | 0.9 | no | 32 | no | Codetext | AllplanAttributes - Sicherheitsklasse: -; Sonnenschutztyp: Movable; g-Wert: 0,51
 | H2 Ebene +1 | WA-DL | 1155Wa 0000121100 | yes | Codetext | m³ | Zimmer- und Holzbauarbeiten | Wand | Außenwand 2-Schalig | WA-DL | 0 | A | 3.75 | 1155HWa0000121097 | NEW | no | yes | 0 | 0.9 | no | 32 | no | Codetext | AllplanAttributes - Sicherheitsklasse: -; Sonnenschutztyp: Movable; g-Wert: 0,51
 | H2 Ebene +1 | WA-LB | 1155Wa 0000121101 | yes | Codetext | m² | Trockenbauarbeiten | Wand | Außenwand 2-Schalig | WA-LB | 0 | A | 3.75 | 1155HWa0000121097 | NEW | no | yes | 0 | 0.9 | no | 32 | no | Codetext | AllplanAttributes - Sicherheitsklasse: -; Sonnenschutztyp: Movable; g-Wert: 0,51
 | H2 Ebene +1 | WA-KL | 1155Wa 0000121102 | yes | Codetext | m² | Zimmer- und Holzbauarbeiten | Wand | Außenwand 2-Schalig | WA-KL | 0 | A | 3.75 | 1155HWa0000121097 | NEW | no | yes | 0 | 0.9 | no | 32 | no | Codetext | AllplanAttributes - Sicherheitsklasse: -; Sonnenschutztyp: Movable; g-Wert: 0,51
 | H2 Ebene +1 | WA-TL | 1155Wa 0000121103 | yes | Codetext | m² | Zimmer- und Holzbauarbeiten | Wand | Außenwand 2-Schalig | WA-TL | 0 | A | 3.75 | 1155HWa0000121097 | NEW | no | yes | 0 | 0.9 | no | 32 | no | Codetext | AllplanAttributes - Sicherheitsklasse: -; Sonnenschutztyp: Movable; g-Wert: 0,51
 | H2 Ebene +1 | WA-HS | 1155Wa 0000121104 | yes | Codetext | m² | Zimmer- und Holzbauarbeiten | Wand | Außenwand 2-Schalig | WA-HS | 0 | A | 3.75 | 1155HWa0000121097 | NEW | no | yes | 0 | 0.9 | no | 32 | no | Codetext | AllplanAttributes - Sicherheitsklasse: -; Sonnenschutztyp: Movable; g-Wert: 0,51
 | H2 Ebene +1 | WA-STB | 1155Wa 0000121150 | yes | Codetext | m² | Zimmer- und Holzbauarbeiten | Wand | Außenwand 2-Schalig | WA-STB | 0 | A | 3.75 | 1155HWa0000121143 | NEW | no | yes | 0 | 0.9 | no | 32 | no | Codetext | AllplanAttributes - Sicherheitsklasse: -; Sonnenschutztyp: Movable; g-Wert: 0,51
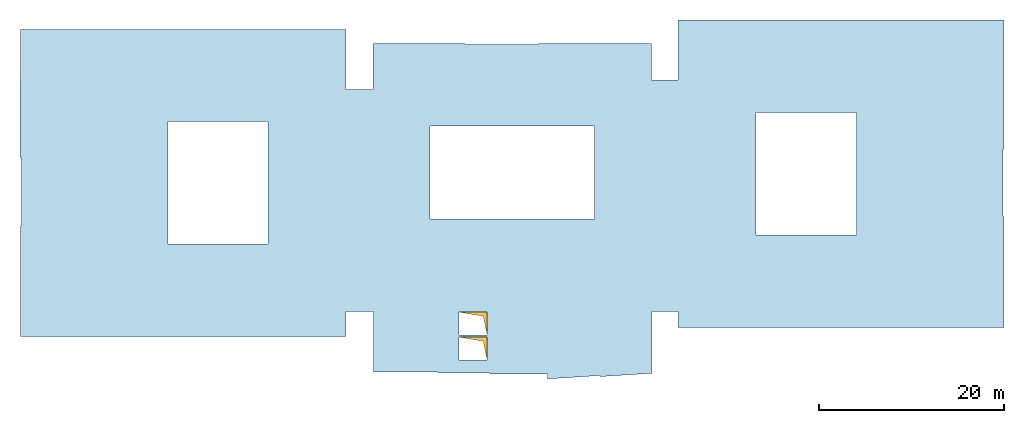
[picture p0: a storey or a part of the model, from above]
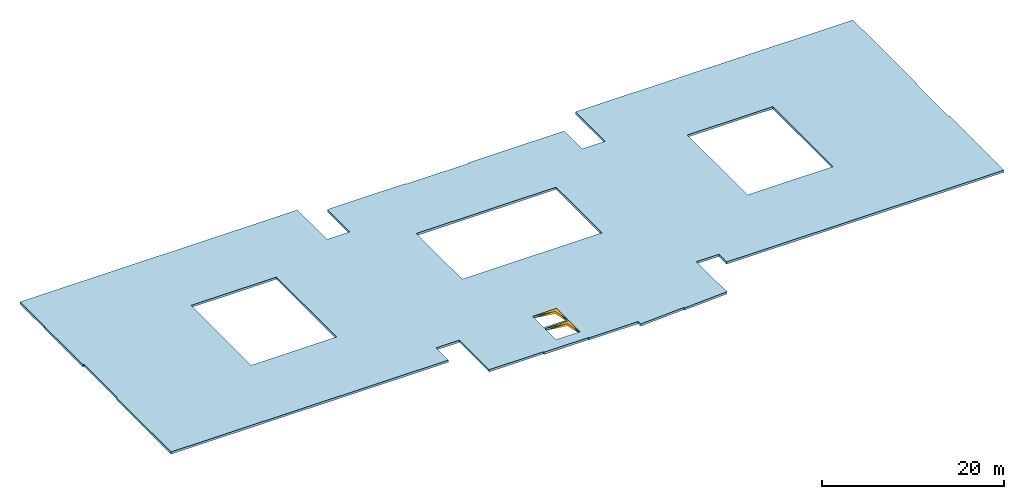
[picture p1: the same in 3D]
Properties of the parts of a building model (IFC4), part 61 of 80

# IfcWall (6826)
Name | In | Material | Allright_Bauteil_ID | 2D Interaktion | Codetext | Abrechnungsart | Gewerk | Objektname | Bezeichnung | AllplanAttributes, Material | Typ = SurfaceSpreadOfFlame | Brandschutzklasse | OKFF | P_ID | Status | LoadBearing | IsExternal | FireRating | ThermalTransmittance (W/K/m2) | Combustible | AcousticRating | Compartmentation | Reference
 | H2 Ebene +1 | WA-DL | 1155Wa 0000121149 | yes | Codetext | m³ | Zimmer- und Holzbauarbeiten | Wand | Außenwand 2-Schalig | WA-DL | 0 | A | 3.75 | 1155HWa0000121143 | NEW | no | yes | 0 | 0.9 | no | 32 | no | Codetext | AllplanAttributes - Sicherheitsklasse: -; Sonnenschutztyp: Movable; g-Wert: 0,51
 | H2 Ebene +1 | WA-LB | 1155Wa 0000121148 | yes | Codetext | m² | Trockenbauarbeiten | Wand | Außenwand 2-Schalig | WA-LB | 0 | A | 3.75 | 1155HWa0000121143 | NEW | no | yes | 0 | 0.9 | no | 32 | no | Codetext | AllplanAttributes - Sicherheitsklasse: -; Sonnenschutztyp: Movable; g-Wert: 0,51
 | H2 Ebene +1 | WA-KL | 1155Wa 0000121147 | yes | Codetext | m² | Zimmer- und Holzbauarbeiten | Wand | Außenwand 2-Schalig | WA-KL | 0 | A | 3.75 | 1155HWa0000121143 | NEW | no | yes | 0 | 0.9 | no | 32 | no | Codetext | AllplanAttributes - Sicherheitsklasse: -; Sonnenschutztyp: Movable; g-Wert: 0,51
 | H2 Ebene +1 | WA-TL | 1155Wa 0000121146 | yes | Codetext | m² | Zimmer- und Holzbauarbeiten | Wand | Außenwand 2-Schalig | WA-TL | 0 | A | 3.75 | 1155HWa0000121143 | NEW | no | yes | 0 | 0.9 | no | 32 | no | Codetext | AllplanAttributes - Sicherheitsklasse: -; Sonnenschutztyp: Movable; g-Wert: 0,51
 | H2 Ebene +1 | WA-HS | 1155Wa 0000121145 | yes | Codetext | m² | Zimmer- und Holzbauarbeiten | Wand | Außenwand 2-Schalig | WA-HS | 0 | A | 3.75 | 1155HWa0000121143 | NEW | no | yes | 0 | 0.9 | no | 32 | no | Codetext | AllplanAttributes - Sicherheitsklasse: -; Sonnenschutztyp: Movable; g-Wert: 0,51
 | H2 Ebene +1 | WA-LB | 1155Wa 0000086111 | yes | Codetext | m² | Trockenbauarbeiten | Wand | Außenwand 7-Schalig | WA-LB | 0 | A | 3.75 | 1155HWa0000086098 | NEW | no | yes | 0 | 0.9 | no | 32 | no | Codetext | AllplanAttributes - Sicherheitsklasse: -; Sonnenschutztyp: Movable; g-Wert: 0,51
 | H2 Ebene +1 | WA-HD | 1155Wa 0000086112 | yes | Codetext | m³ | Zimmer- und Holzbauarbeiten | Wand | Außenwand 7-Schalig | WA-HD | 0 | A | 3.75 | 1155HWa0000086098 | NEW | no | yes | 0 | 0.9 | no | 32 | no | Codetext | AllplanAttributes - Sicherheitsklasse: -; Sonnenschutztyp: Movable; g-Wert: 0,51; ash W_laufende Nr. Statik: 2 (W 2.0/ 2.1/ 2.2)
 | H2 Ebene +1 | WA-DL | 1155Wa 0000086113 | yes | Codetext | m³ | Zimmer- und Holzbauarbeiten | Wand | Außenwand 7-Schalig | WA-DL | 0 | A | 3.75 | 1155HWa0000086098 | NEW | no | yes | 0 | 0.9 | no | 32 | no | Codetext | AllplanAttributes - Sicherheitsklasse: -; Sonnenschutztyp: Movable; g-Wert: 0,51
 | H2 Ebene +1 | WA-LB | 1155Wa 0000086114 | yes | Codetext | m² | Trockenbauarbeiten | Wand | Außenwand 7-Schalig | WA-LB | 0 | A | 3.75 | 1155HWa0000086098 | NEW | no | yes | 0 | 0.9 | no | 32 | no | Codetext | AllplanAttributes - Sicherheitsklasse: -; Sonnenschutztyp: Movable; g-Wert: 0,51
 | H2 Ebene +1 | WA-KL | 1155Wa 0000086115 | yes | Codetext | m² | Zimmer- und Holzbauarbeiten | Wand | Außenwand 7-Schalig | WA-KL | 0 | A | 3.75 | 1155HWa0000086098 | NEW | no | yes | 0 | 0.9 | no | 32 | no | Codetext | AllplanAttributes - Sicherheitsklasse: -; Sonnenschutztyp: Movable; g-Wert: 0,51
 | H2 Ebene +1 | WA-TL | 1155Wa 0000086116 | yes | Codetext | m² | Zimmer- und Holzbauarbeiten | Wand | Außenwand 7-Schalig | WA-TL | 0 | A | 3.75 | 1155HWa0000086098 | NEW | no | yes | 0 | 0.9 | no | 32 | no | Codetext | AllplanAttributes - Sicherheitsklasse: -; Sonnenschutztyp: Movable; g-Wert: 0,51
 | H2 Ebene +1 | WA-HS | 1155Wa 0000086117 | yes | Codetext | m² | Zimmer- und Holzbauarbeiten | Wand | Außenwand 7-Schalig | WA-HS | 0 | A | 3.75 | 1155HWa0000086098 | NEW | no | yes | 0 | 0.9 | no | 32 | no | Codetext | AllplanAttributes - Sicherheitsklasse: -; Sonnenschutztyp: Movable; g-Wert: 0,51
 | H2 Ebene +1 | WA-LB | 1155Wa 0000087571 | yes | Codetext | m² | Trockenbauarbeiten | Wand | Außenwand 7-Schalig | WA-LB | 0 | A | 3.75 | 1155HWa0000087563 | NEW | no | yes | 0 | 0.9 | no | 32 | no | Codetext | AllplanAttributes - Sicherheitsklasse: -; Sonnenschutztyp: Movable; g-Wert: 0,51
 | H2 Ebene +1 | WA-HD | 1155Wa 0000087570 | yes | Codetext | m³ | Zimmer- und Holzbauarbeiten | Wand | Außenwand 7-Schalig | WA-HD | 0 | A | 3.75 | 1155HWa0000087563 | NEW | no | yes | 0 | 0.9 | no | 32 | no | Codetext | AllplanAttributes - Sicherheitsklasse: -; Sonnenschutztyp: Movable; g-Wert: 0,51; ash W_laufende Nr. Statik: 2 (W 2.0/ 2.1/ 2.2)
 | H2 Ebene +1 | WA-DL | 1155Wa 0000087569 | yes | Codetext | m³ | Zimmer- und Holzbauarbeiten | Wand | Außenwand 7-Schalig | WA-DL | 0 | A | 3.75 | 1155HWa0000087563 | NEW | no | yes | 0 | 0.9 | no | 32 | no | Codetext | AllplanAttributes - Sicherheitsklasse: -; Sonnenschutztyp: Movable; g-Wert: 0,51
 | H2 Ebene +1 | WA-LB | 1155Wa 0000087568 | yes | Codetext | m² | Trockenbauarbeiten | Wand | Außenwand 7-Schalig | WA-LB | 0 | A | 3.75 | 1155HWa0000087563 | NEW | no | yes | 0 | 0.9 | no | 32 | no | Codetext | AllplanAttributes - Sicherheitsklasse: -; Sonnenschutztyp: Movable; g-Wert: 0,51
 | H2 Ebene +1 | WA-KL | 1155Wa 0000087567 | yes | Codetext | m² | Zimmer- und Holzbauarbeiten | Wand | Außenwand 7-Schalig | WA-KL | 0 | A | 3.75 | 1155HWa0000087563 | NEW | no | yes | 0 | 0.9 | no | 32 | no | Codetext | AllplanAttributes - Sicherheitsklasse: -; Sonnenschutztyp: Movable; g-Wert: 0,51
 | H2 Ebene +1 | WA-TL | 1155Wa 0000087566 | yes | Codetext | m² | Zimmer- und Holzbauarbeiten | Wand | Außenwand 7-Schalig | WA-TL | 0 | A | 3.75 | 1155HWa0000087563 | NEW | no | yes | 0 | 0.9 | no | 32 | no | Codetext | AllplanAttributes - Sicherheitsklasse: -; Sonnenschutztyp: Movable; g-Wert: 0,51
 | H2 Ebene +1 | WA-HS | 1155Wa 0000087565 | yes | Codetext | m² | Zimmer- und Holzbauarbeiten | Wand | Außenwand 7-Schalig | WA-HS | 0 | A | 3.75 | 1155HWa0000087563 | NEW | no | yes | 0 | 0.9 | no | 32 | no | Codetext | AllplanAttributes - Sicherheitsklasse: -; Sonnenschutztyp: Movable; g-Wert: 0,51
 | H2 Ebene +1 | WA-LB | 1155Wa 0000001663 | yes | Codetext | m² | Trockenbauarbeiten | Wand | Außenwand 7-Schalig | WA-LB | 0 | A | 3.75 | 1155HWa0000001631 | NEW | no | yes | 0 | 0.9 | no | 32 | no | Codetext | AllplanAttributes - Sicherheitsklasse: -; Sonnenschutztyp: Movable; g-Wert: 0,51
 | H2 Ebene +1 | WA-HD | 1155Wa 0000001665 | yes | Codetext | m³ | Zimmer- und Holzbauarbeiten | Wand | Außenwand 7-Schalig | WA-HD | 0 | A | 3.75 | 1155HWa0000001631 | NEW | no | yes | 0 | 0.9 | no | 32 | no | Codetext | AllplanAttributes - Sicherheitsklasse: -; Sonnenschutztyp: Movable; g-Wert: 0,51; ash W_laufende Nr. Statik: 2 (W 2.0/ 2.1/ 2.2)
 | H2 Ebene +1 | WA-DL | 1155Wa 0000001667 | yes | Codetext | m³ | Zimmer- und Holzbauarbeiten | Wand | Außenwand 7-Schalig | WA-DL | 0 | A | 3.75 | 1155HWa0000001631 | NEW | no | yes | 0 | 0.9 | no | 32 | no | Codetext | AllplanAttributes - Sicherheitsklasse: -; Sonnenschutztyp: Movable; g-Wert: 0,51
 | H2 Ebene +1 | WA-LB | 1155Wa 0000001669 | yes | Codetext | m² | Trockenbauarbeiten | Wand | Außenwand 7-Schalig | WA-LB | 0 | A | 3.75 | 1155HWa0000001631 | NEW | no | yes | 0 | 0.9 | no | 32 | no | Codetext | AllplanAttributes - Sicherheitsklasse: -; Sonnenschutztyp: Movable; g-Wert: 0,51
 | H2 Ebene +1 | WA-KL | 1155Wa 0000001671 | yes | Codetext | m² | Zimmer- und Holzbauarbeiten | Wand | Außenwand 7-Schalig | WA-KL | 0 | A | 3.75 | 1155HWa0000001631 | NEW | no | yes | 0 | 0.9 | no | 32 | no | Codetext | AllplanAttributes - Sicherheitsklasse: -; Sonnenschutztyp: Movable; g-Wert: 0,51
 | H2 Ebene +1 | WA-TL | 1155Wa 0000001673 | yes | Codetext | m² | Zimmer- und Holzbauarbeiten | Wand | Außenwand 7-Schalig | WA-TL | 0 | A | 3.75 | 1155HWa0000001631 | NEW | no | yes | 0 | 0.9 | no | 32 | no | Codetext | AllplanAttributes - Sicherheitsklasse: -; Sonnenschutztyp: Movable; g-Wert: 0,51
 | H2 Ebene +1 | WA-HS | 1155Wa 0000001675 | yes | Codetext | m² | Zimmer- und Holzbauarbeiten | Wand | Außenwand 7-Schalig | WA-HS | 0 | A | 3.75 | 1155HWa0000001631 | NEW | no | yes | 0 | 0.9 | no | 32 | no | Codetext | AllplanAttributes - Sicherheitsklasse: -; Sonnenschutztyp: Movable; g-Wert: 0,51
2x Gipsfaserplatte | H2 Ebene +1 | WA-LB | 1155Wa 0000144135 | yes |  | m² | Trockenbauarbeiten | Wand | 2x Gipsfaserplatte | WA-LB |  |  | 3.75 | 1155HWa0000144134 | NEW | no | yes | 0 | 0.9 |  | 32 | AllplanAttributes - Sicherheitsklasse: -; Sonnenschutztyp: Movable; g-Wert: 0,51
Holzständer + Zwischendämmung | H2 Ebene +1 | WA-HD | 1155Wa 0000144136 | yes |  | m³ | Zimmer- und Holzbauarbeiten | Wand | Holzständer + Zwischendämmung | WA-HD |  |  | 3.75 | 1155HWa0000144134 | NEW | no | yes | 0 | 0.9 |  | 32 | AllplanAttributes - Sicherheitsklasse: -; Sonnenschutztyp: Movable; g-Wert: 0,51; ash W_laufende Nr. Statik: 2 (W 2.0/ 2.1/ 2.2)
Staffel + Zwischendämmung | H2 Ebene +1 | WA-DL | 1155Wa 0000144137 | yes |  | m³ | Zimmer- und Holzbauarbeiten | Wand | Staffel + Zwischendämmung | WA-DL |  |  | 3.75 | 1155HWa0000144134 | NEW | no | yes | 0 | 0.9 |  | 32 | AllplanAttributes - Sicherheitsklasse: -; Sonnenschutztyp: Movable; g-Wert: 0,51
 | H2 Ebene +1 | WA-LB | 1155Wa 0000144138 | yes | Codetext | m² | Trockenbauarbeiten | Wand | Außenwand 7-Schalig | WA-LB | 0 | A | 3.75 | 1155HWa0000144134 | NEW | no | yes | 0 | 0.9 | no | 32 | no | Codetext | AllplanAttributes - Sicherheitsklasse: -; Sonnenschutztyp: Movable; g-Wert: 0,51
Konterlattung | H2 Ebene +1 | WA-KL | 1155Wa 0000144139 | yes |  | m² | Zimmer- und Holzbauarbeiten | Wand | Konterlattung | WA-KL |  |  | 3.75 | 1155HWa0000144134 | NEW | no | yes | 0 | 0.9 |  | 32 | AllplanAttributes - Sicherheitsklasse: -; Sonnenschutztyp: Movable; g-Wert: 0,51
Traglattung | H2 Ebene +1 | WA-TL | 1155Wa 0000144140 | yes |  | m² | Zimmer- und Holzbauarbeiten | Wand | Traglattung | WA-TL |  |  | 3.75 | 1155HWa0000144134 | NEW | no | yes | 0 | 0.9 |  | 32 | AllplanAttributes - Sicherheitsklasse: -; Sonnenschutztyp: Movable; g-Wert: 0,51
Holzschindel | H2 Ebene +1 | WA-HS | 1155Wa 0000144141 | yes |  | m² | Zimmer- und Holzbauarbeiten | Wand | Holzschindel | WA-HS |  |  | 3.75 | 1155HWa0000144134 | NEW | no | yes | 0 | 0.9 |  | 32 | AllplanAttributes - Sicherheitsklasse: -; Sonnenschutztyp: Movable; g-Wert: 0,51
2x Gipsfaserplatte | H2 Ebene +1 | WA-LB | 1155Wa 0000144096 | yes |  | m² | Trockenbauarbeiten | Wand | 2x Gipsfaserplatte | WA-LB |  |  | 3.75 | 1155HWa0000144095 | NEW | no | yes | 0 | 0.9 |  | 32 | AllplanAttributes - Sicherheitsklasse: -; Sonnenschutztyp: Movable; g-Wert: 0,51
Holzständer + Zwischendämmung | H2 Ebene +1 | WA-HD | 1155Wa 0000144097 | yes |  | m³ | Zimmer- und Holzbauarbeiten | Wand | Holzständer + Zwischendämmung | WA-HD |  |  | 3.75 | 1155HWa0000144095 | NEW | no | yes | 0 | 0.9 |  | 32 | AllplanAttributes - Sicherheitsklasse: -; Sonnenschutztyp: Movable; g-Wert: 0,51; ash W_laufende Nr. Statik: 2 (W 2.0/ 2.1/ 2.2)
Staffel + Zwischendämmung | H2 Ebene +1 | WA-DL | 1155Wa 0000144098 | yes |  | m³ | Zimmer- und Holzbauarbeiten | Wand | Staffel + Zwischendämmung | WA-DL |  |  | 3.75 | 1155HWa0000144095 | NEW | no | yes | 0 | 0.9 |  | 32 | AllplanAttributes - Sicherheitsklasse: -; Sonnenschutztyp: Movable; g-Wert: 0,51
 | H2 Ebene +1 | WA-LB | 1155Wa 0000144099 | yes | Codetext | m² | Trockenbauarbeiten | Wand | Außenwand 7-Schalig | WA-LB | 0 | A | 3.75 | 1155HWa0000144095 | NEW | no | yes | 0 | 0.9 | no | 32 | no | Codetext | AllplanAttributes - Sicherheitsklasse: -; Sonnenschutztyp: Movable; g-Wert: 0,51
Konterlattung | H2 Ebene +1 | WA-KL | 1155Wa 0000144100 | yes |  | m² | Zimmer- und Holzbauarbeiten | Wand | Konterlattung | WA-KL |  |  | 3.75 | 1155HWa0000144095 | NEW | no | yes | 0 | 0.9 |  | 32 | AllplanAttributes - Sicherheitsklasse: -; Sonnenschutztyp: Movable; g-Wert: 0,51
Traglattung | H2 Ebene +1 | WA-TL | 1155Wa 0000144101 | yes |  | m² | Zimmer- und Holzbauarbeiten | Wand | Traglattung | WA-TL |  |  | 3.75 | 1155HWa0000144095 | NEW | no | yes | 0 | 0.9 |  | 32 | AllplanAttributes - Sicherheitsklasse: -; Sonnenschutztyp: Movable; g-Wert: 0,51
Holzschindel | H2 Ebene +1 | WA-HS | 1155Wa 0000144102 | yes |  | m² | Zimmer- und Holzbauarbeiten | Wand | Holzschindel | WA-HS |  |  | 3.75 | 1155HWa0000144095 | NEW | no | yes | 0 | 0.9 |  | 32 | AllplanAttributes - Sicherheitsklasse: -; Sonnenschutztyp: Movable; g-Wert: 0,51
 | H2 Ebene +1 | WI-STB | 1155Wa 0000010295 | yes | Codetext | m² | Zimmer- und Holzbauarbeiten | Wand | Innenwand 1-Schalig | WI-STB | 0 | A | 3.75 | 1155HWa0000010253 | NEW | no | no | 0 | 0.9 | no | 32 | no | Codetext | AllplanAttributes - Ortscode_Geschoßbezeichnung: E01; Sicherheitsklasse: -; Sonnenschutztyp: Movable; g-Wert: 0,51
 | H2 Ebene +1 | WA-LB | 1155Wa 0000084597 | yes | Codetext | m² | Trockenbauarbeiten | Wand | Außenwand 7-Schalig | WA-LB | 0 | A | 3.75 | 1155HWa0000084596 | NEW | no | yes | 0 | 0.9 | no | 32 | no | Codetext | AllplanAttributes - Sicherheitsklasse: -; Sonnenschutztyp: Movable; g-Wert: 0,51
 | H2 Ebene +1 | WA-HD | 1155Wa 0000084598 | yes | Codetext | m³ | Zimmer- und Holzbauarbeiten | Wand | Außenwand 7-Schalig | WA-HD | 0 | A | 3.75 | 1155HWa0000084596 | NEW | no | yes | 0 | 0.9 | no | 32 | no | Codetext | AllplanAttributes - Sicherheitsklasse: -; Sonnenschutztyp: Movable; g-Wert: 0,51; ash W_laufende Nr. Statik: 2 (W 2.0/ 2.1/ 2.2)
 | H2 Ebene +1 | WA-DL | 1155Wa 0000084599 | yes | Codetext | m³ | Zimmer- und Holzbauarbeiten | Wand | Außenwand 7-Schalig | WA-DL | 0 | A | 3.75 | 1155HWa0000084596 | NEW | no | yes | 0 | 0.9 | no | 32 | no | Codetext | AllplanAttributes - Sicherheitsklasse: -; Sonnenschutztyp: Movable; g-Wert: 0,51
 | H2 Ebene +1 | WA-LB | 1155Wa 0000084600 | yes | Codetext | m² | Trockenbauarbeiten | Wand | Außenwand 7-Schalig | WA-LB | 0 | A | 3.75 | 1155HWa0000084596 | NEW | no | yes | 0 | 0.9 | no | 32 | no | Codetext | AllplanAttributes - Sicherheitsklasse: -; Sonnenschutztyp: Movable; g-Wert: 0,51
 | H2 Ebene +1 | WA-KL | 1155Wa 0000084601 | yes | Codetext | m² | Zimmer- und Holzbauarbeiten | Wand | Außenwand 7-Schalig | WA-KL | 0 | A | 3.75 | 1155HWa0000084596 | NEW | no | yes | 0 | 0.9 | no | 32 | no | Codetext | AllplanAttributes - Sicherheitsklasse: -; Sonnenschutztyp: Movable; g-Wert: 0,51
 | H2 Ebene +1 | WA-TL | 1155Wa 0000084602 | yes | Codetext | m² | Zimmer- und Holzbauarbeiten | Wand | Außenwand 7-Schalig | WA-TL | 0 | A | 3.75 | 1155HWa0000084596 | NEW | no | yes | 0 | 0.9 | no | 32 | no | Codetext | AllplanAttributes - Sicherheitsklasse: -; Sonnenschutztyp: Movable; g-Wert: 0,51
 | H2 Ebene +1 | WA-HS | 1155Wa 0000084603 | yes | Codetext | m² | Zimmer- und Holzbauarbeiten | Wand | Außenwand 7-Schalig | WA-HS | 0 | A | 3.75 | 1155HWa0000084596 | NEW | no | yes | 0 | 0.9 | no | 32 | no | Codetext | AllplanAttributes - Sicherheitsklasse: -; Sonnenschutztyp: Movable; g-Wert: 0,51
2x Gipsfaserplatte | H2 Ebene +1 | WA-LB | 1155Wa 0000001712 | yes |  | m² | Trockenbauarbeiten | Wand | 2x Gipsfaserplatte | WA-LB |  |  | 3.75 | 1155HWa0000001569 | NEW | no | yes | 0 | 0.9 |  | 32 | AllplanAttributes - Sicherheitsklasse: -; Sonnenschutztyp: Movable; g-Wert: 0,51
Holzständer + Zwischendämmung | H2 Ebene +1 | WA-HD | 1155Wa 0000001714 | yes |  | m³ | Zimmer- und Holzbauarbeiten | Wand | Holzständer + Zwischendämmung | WA-HD |  |  | 3.75 | 1155HWa0000001569 | NEW | no | yes | 0 | 0.9 |  | 32 | AllplanAttributes - Sicherheitsklasse: -; Sonnenschutztyp: Movable; g-Wert: 0,51; ash W_laufende Nr. Statik: 2 (W 2.0/ 2.1/ 2.2)
Staffel + Zwischendämmung | H2 Ebene +1 | WA-DL | 1155Wa 0000001716 | yes |  | m³ | Zimmer- und Holzbauarbeiten | Wand | Staffel + Zwischendämmung | WA-DL |  |  | 3.75 | 1155HWa0000001569 | NEW | no | yes | 0 | 0.9 |  | 32 | AllplanAttributes - Sicherheitsklasse: -; Sonnenschutztyp: Movable; g-Wert: 0,51
 | H2 Ebene +1 | WA-LB | 1155Wa 0000001718 | yes | Codetext | m² | Trockenbauarbeiten | Wand | Außenwand 7-Schalig | WA-LB | 0 | A | 3.75 | 1155HWa0000001569 | NEW | no | yes | 0 | 0.9 | no | 32 | no | Codetext | AllplanAttributes - Sicherheitsklasse: -; Sonnenschutztyp: Movable; g-Wert: 0,51
Konterlattung | H2 Ebene +1 | WA-KL | 1155Wa 0000001720 | yes |  | m² | Zimmer- und Holzbauarbeiten | Wand | Konterlattung | WA-KL |  |  | 3.75 | 1155HWa0000001569 | NEW | no | yes | 0 | 0.9 |  | 32 | AllplanAttributes - Sicherheitsklasse: -; Sonnenschutztyp: Movable; g-Wert: 0,51
Traglattung | H2 Ebene +1 | WA-TL | 1155Wa 0000001722 | yes |  | m² | Zimmer- und Holzbauarbeiten | Wand | Traglattung | WA-TL |  |  | 3.75 | 1155HWa0000001569 | NEW | no | yes | 0 | 0.9 |  | 32 | AllplanAttributes - Sicherheitsklasse: -; Sonnenschutztyp: Movable; g-Wert: 0,51
Holzschindel | H2 Ebene +1 | WA-HS | 1155Wa 0000001724 | yes |  | m² | Zimmer- und Holzbauarbeiten | Wand | Holzschindel | WA-HS |  |  | 3.75 | 1155HWa0000001569 | NEW | no | yes | 0 | 0.9 |  | 32 | AllplanAttributes - Sicherheitsklasse: -; Sonnenschutztyp: Movable; g-Wert: 0,51
2x Gipsfaserplatte | H2 Ebene +1 | WA-LB | 1155Wa 0000197819 | yes |  | m² | Trockenbauarbeiten | Wand | 2x Gipsfaserplatte | WA-LB |  |  | 3.75 | 1155HWa0000197809 | NEW | no | yes | 0 | 0.9 |  | 32 | AllplanAttributes - Sicherheitsklasse: -; Sonnenschutztyp: Movable; g-Wert: 0,51
2x Gipsfaserplatte | H2 Ebene +1 | WA-LB | 1155Wa 0000197818 | yes |  | m² | Trockenbauarbeiten | Wand | 2x Gipsfaserplatte | WA-LB |  |  | 3.75 | 1155HWa0000197809 | NEW | no | yes | 0 | 0.9 |  | 32 | AllplanAttributes - Sicherheitsklasse: -; Sonnenschutztyp: Movable; g-Wert: 0,51
Holzständer + Zwischendämmung | H2 Ebene +1 | WA-DL | 1155Wa 0000197817 | yes |  | m³ | Zimmer- und Holzbauarbeiten | Wand | Holzständer + Zwischendämmung | WA-DL |  |  | 3.75 | 1155HWa0000197809 | NEW | no | yes | 0 | 0.9 |  | 32 | AllplanAttributes - Sicherheitsklasse: -; Sonnenschutztyp: Movable; g-Wert: 0,51; ash W_laufende Nr. Statik: 6 (W 6.0)
 | H2 Ebene +1 | WA-LB | 1155Wa 0000197816 | yes | Codetext | m² | Trockenbauarbeiten | Wand | Außenwand 7-Schalig | WA-LB | 0 | A | 3.75 | 1155HWa0000197809 | NEW | no | yes | 0 | 0.9 | no | 32 | no | Codetext | AllplanAttributes - Sicherheitsklasse: -; Sonnenschutztyp: Movable; g-Wert: 0,51
 | H2 Ebene +1 | WA-LB | 1155Wa 0000197811 | yes | Codetext | m² | Trockenbauarbeiten | Wand | Außenwand 7-Schalig | WA-LB | 0 | A | 3.75 | 1155HWa0000197809 | NEW | no | yes | 0 | 0.9 | no | 32 | no | Codetext | AllplanAttributes - Sicherheitsklasse: -; Sonnenschutztyp: Movable; g-Wert: 0,51
Staffel + Zwischendämmung | H2 Ebene +1 | WA-DL | 1155Wa 0000197812 | yes |  | m³ | Zimmer- und Holzbauarbeiten | Wand | Staffel + Zwischendämmung | WA-DL |  |  | 3.75 | 1155HWa0000197809 | NEW | no | yes | 0 | 0.9 |  | 32 | AllplanAttributes - Sicherheitsklasse: -; Sonnenschutztyp: Movable; g-Wert: 0,51
Konterlattung | H2 Ebene +1 | WA-KL | 1155Wa 0000197813 | yes |  | m² | Zimmer- und Holzbauarbeiten | Wand | Konterlattung | WA-KL |  |  | 3.75 | 1155HWa0000197809 | NEW | no | yes | 0 | 0.9 |  | 32 | AllplanAttributes - Sicherheitsklasse: -; Sonnenschutztyp: Movable; g-Wert: 0,51
Traglattung | H2 Ebene +1 | WA-TL | 1155Wa 0000197814 | yes |  | m² | Zimmer- und Holzbauarbeiten | Wand | Traglattung | WA-TL |  |  | 3.75 | 1155HWa0000197809 | NEW | no | yes | 0 | 0.9 |  | 32 | AllplanAttributes - Sicherheitsklasse: -; Sonnenschutztyp: Movable; g-Wert: 0,51
Holzschindel | H2 Ebene +1 | WA-HS | 1155Wa 0000197815 | yes |  | m² | Zimmer- und Holzbauarbeiten | Wand | Holzschindel | WA-HS |  |  | 3.75 | 1155HWa0000197809 | NEW | no | yes | 0 | 0.9 |  | 32 | AllplanAttributes - Sicherheitsklasse: -; Sonnenschutztyp: Movable; g-Wert: 0,51
 | H2 Ebene +1 | WA-LB | 1155Wa 0813745900 | yes | Codetext | m² | Trockenbauarbeiten | Wand | Außenwand 7-Schalig | WA-LB | 0 | A | 3.75 | 1155HWa0000192367 | NEW | no | yes | 0 | 0.9 | no | 35 | no | Codetext | AllplanAttributes - Sicherheitsklasse: -; Sonnenschutztyp: Movable; g-Wert: 0,51
 | H2 Ebene +1 | WA-HD | 1155Wa 0813745901 | yes | Codetext | m³ | Zimmer- und Holzbauarbeiten | Wand | Außenwand 7-Schalig | WA-HD | 0 | A | 3.75 | 1155HWa0000192367 | NEW | no | yes | 0 | 0.9 | no | 35 | no | Codetext | AllplanAttributes - Sicherheitsklasse: -; Sonnenschutztyp: Movable; g-Wert: 0,51; ash W_laufende Nr. Statik: 2 (W 2.0/ 2.1/ 2.2)
 | H2 Ebene +1 | WA-DL | 1155Wa 0813745902 | yes | Codetext | m³ | Zimmer- und Holzbauarbeiten | Wand | Außenwand 7-Schalig | WA-DL | 0 | A | 3.75 | 1155HWa0000192367 | NEW | no | yes | 0 | 0.9 | no | 35 | no | Codetext | AllplanAttributes - Sicherheitsklasse: -; Sonnenschutztyp: Movable; g-Wert: 0,51
 | H2 Ebene +1 | WA-LB | 1155Wa 0813745903 | yes | Codetext | m² | Trockenbauarbeiten | Wand | Außenwand 7-Schalig | WA-LB | 0 | A | 3.75 | 1155HWa0000192367 | NEW | no | yes | 0 | 0.9 | no | 35 | no | Codetext | AllplanAttributes - Sicherheitsklasse: -; Sonnenschutztyp: Movable; g-Wert: 0,51
 | H2 Ebene +1 | WA-KL | 1155Wa 0813745904 | yes | Codetext | m² | Zimmer- und Holzbauarbeiten | Wand | Außenwand 7-Schalig | WA-KL | 0 | A | 3.75 | 1155HWa0000192367 | NEW | no | yes | 0 | 0.9 | no | 35 | no | Codetext | AllplanAttributes - Sicherheitsklasse: -; Sonnenschutztyp: Movable; g-Wert: 0,51
 | H2 Ebene +1 | WA-TL | 1155Wa 0813745905 | yes | Codetext | m² | Zimmer- und Holzbauarbeiten | Wand | Außenwand 7-Schalig | WA-TL | 0 | A | 3.75 | 1155HWa0000192367 | NEW | no | yes | 0 | 0.9 | no | 35 | no | Codetext | AllplanAttributes - Sicherheitsklasse: -; Sonnenschutztyp: Movable; g-Wert: 0,51
 | H2 Ebene +1 | WA-HS | 1155Wa 0813745906 | yes | Codetext | m² | Zimmer- und Holzbauarbeiten | Wand | Außenwand 7-Schalig | WA-HS | 0 | A | 3.75 | 1155HWa0000192367 | NEW | no | yes | 0 | 0.9 | no | 35 | no | Codetext | AllplanAttributes - Sicherheitsklasse: -; Sonnenschutztyp: Movable; g-Wert: 0,51
 | H2 Ebene +1 | WA-LB | 1155Wa 0000001277 | yes | Codetext | m² | Trockenbauarbeiten | Wand | Außenwand 7-Schalig | WA-LB | 0 | A | 3.75 | 1155HWa0000000029 | NEW | no | yes | 0 | 0.9 | no | 32 | no | Codetext | AllplanAttributes - Sicherheitsklasse: -; Sonnenschutztyp: Movable; g-Wert: 0,51
 | H2 Ebene +1 | WA-HD | 1155Wa 0000001301 | yes | Codetext | m³ | Zimmer- und Holzbauarbeiten | Wand | Außenwand 7-Schalig | WA-HD | 0 | A | 3.75 | 1155HWa0000000029 | NEW | no | yes | 0 | 0.9 | no | 32 | no | Codetext | AllplanAttributes - ash D_Detailverweis: DT C/D; ash D_Plannummer: D1851; Sicherheitsklasse: -; Sonnenschutztyp: Movable; g-Wert: 0,51; ash W_laufende Nr. Statik: 5 (W 4.0)
 | H2 Ebene +1 | WA-DL | 1155Wa 0000001303 | yes | Codetext | m³ | Zimmer- und Holzbauarbeiten | Wand | Außenwand 7-Schalig | WA-DL | 0 | A | 3.75 | 1155HWa0000000029 | NEW | no | yes | 0 | 0.9 | no | 32 | no | Codetext | AllplanAttributes - Sicherheitsklasse: -; Sonnenschutztyp: Movable; g-Wert: 0,51
 | H2 Ebene +1 | WA-LB | 1155Wa 0000001305 | yes | Codetext | m² | Trockenbauarbeiten | Wand | Außenwand 7-Schalig | WA-LB | 0 | A | 3.75 | 1155HWa0000000029 | NEW | no | yes | 0 | 0.9 | no | 32 | no | Codetext | AllplanAttributes - Sicherheitsklasse: -; Sonnenschutztyp: Movable; g-Wert: 0,51
 | H2 Ebene +1 | WA-KL | 1155Wa 0000001307 | yes | Codetext | m² | Zimmer- und Holzbauarbeiten | Wand | Außenwand 7-Schalig | WA-KL | 0 | A | 3.75 | 1155HWa0000000029 | NEW | no | yes | 0 | 0.9 | no | 32 | no | Codetext | AllplanAttributes - Sicherheitsklasse: -; Sonnenschutztyp: Movable; g-Wert: 0,51
 | H2 Ebene +1 | WA-TL | 1155Wa 0000001309 | yes | Codetext | m² | Zimmer- und Holzbauarbeiten | Wand | Außenwand 7-Schalig | WA-TL | 0 | A | 3.75 | 1155HWa0000000029 | NEW | no | yes | 0 | 0.9 | no | 32 | no | Codetext | AllplanAttributes - Sicherheitsklasse: -; Sonnenschutztyp: Movable; g-Wert: 0,51
Keramikschindel | H2 Ebene +1 | WA-HS | 1155Wa 0000001311 | yes | Codetext | m² | Zimmer- und Holzbauarbeiten | Wand | Keramikschindel | WA-HS | 0 | A | 3.75 | 1155HWa0000000029 | NEW | no | yes | 0 | 0.9 | no | 32 | no | Codetext | AllplanAttributes - Sicherheitsklasse: -; Sonnenschutztyp: Movable; g-Wert: 0,51
 | H2 Ebene +1 | WA-STB | 1155Wa 0000010261 | yes |  | m² | Zimmer- und Holzbauarbeiten | Wand | Außenwand 2-Schalig | WA-STB |  |  | 3.75 | 1155HWa0000010251 | NEW | no |  | 0 | 0.9 |  | 32 | AllplanAttributes - Sicherheitsklasse: -; Sonnenschutztyp: Movable; g-Wert: 0,51
 | H2 Ebene +1 | WA-DL | 1155Wa 0000010269 | yes |  | m³ | Zimmer- und Holzbauarbeiten | Wand | Außenwand 2-Schalig | WA-DL |  |  | 3.75 | 1155HWa0000010251 | NEW | no |  | 0 | 0.9 |  | 32 | AllplanAttributes - Sicherheitsklasse: -; Sonnenschutztyp: Movable; g-Wert: 0,51
 | H2 Ebene +1 | WA-LB | 1155Wa 0000010267 | yes | Codetext | m² | Trockenbauarbeiten | Wand | Außenwand 2-Schalig | WA-LB | 0 | A | 3.75 | 1155HWa0000010251 | NEW | no | yes | 0 | 0.9 | no | 32 | no | Codetext | AllplanAttributes - Sicherheitsklasse: -; Sonnenschutztyp: Movable; g-Wert: 0,51
 | H2 Ebene +1 | WA-TL | 1155Wa 0000010265 | yes |  | m² | Zimmer- und Holzbauarbeiten | Wand | Außenwand 2-Schalig | WA-TL |  |  | 3.75 | 1155HWa0000010251 | NEW | no |  | 0 | 0.9 |  | 32 | AllplanAttributes - Sicherheitsklasse: -; Sonnenschutztyp: Movable; g-Wert: 0,51
Traglattung | H2 Ebene +1 | WA-TL | 1155Wa 0000010263 | yes |  | m² | Zimmer- und Holzbauarbeiten | Wand | Traglattung | WA-TL |  |  | 3.75 | 1155HWa0000010251 | NEW | no | yes | 0 | 0.9 |  | 32 | AllplanAttributes - Sicherheitsklasse: -; Sonnenschutztyp: Movable; g-Wert: 0,51
Keramikschindel | H2 Ebene +1 | WA-HS | 1155Wa 0000060173 | yes |  | m² | Zimmer- und Holzbauarbeiten | Wand | Keramikschindel | WA-HS |  |  | 3.75 | 1155HWa0000010251 | NEW | no |  | 0 | 0.9 |  | 32 | AllplanAttributes - Sicherheitsklasse: -; Sonnenschutztyp: Movable; g-Wert: 0,51
 | H2 Ebene +1 | WA-LB | 1155Wa 0000200048 | yes | Codetext | m² | Trockenbauarbeiten | Wand | Außenwand 7-Schalig | WA-LB | 0 | A | 3.75 | 1155HWa0000199934 | NEW | no | yes | 0 | 0.9 | no | 32 | no | Codetext | AllplanAttributes - ash D_Detailverweis: PL 1850; Sicherheitsklasse: -; Sonnenschutztyp: Movable; g-Wert: 0,51
 | H2 Ebene +1 | WA-HD | 1155Wa 0000200047 | yes | Codetext | m³ | Zimmer- und Holzbauarbeiten | Wand | Außenwand 7-Schalig | WA-HD | 0 | A | 3.75 | 1155HWa0000199934 | NEW | no | yes | 0 | 0.9 | no | 32 | no | Codetext | AllplanAttributes - ash D_Detailverweis: PL 1850; Sicherheitsklasse: -; Sonnenschutztyp: Movable; g-Wert: 0,51; ash W_laufende Nr. Statik: 2 (W 2.0/ 2.1/ 2.2)
 | H2 Ebene +1 | WA-DL | 1155Wa 0000200046 | yes | Codetext | m³ | Zimmer- und Holzbauarbeiten | Wand | Außenwand 7-Schalig | WA-DL | 0 | A | 3.75 | 1155HWa0000199934 | NEW | no | yes | 0 | 0.9 | no | 32 | no | Codetext | AllplanAttributes - ash D_Detailverweis: PL 1850; Sicherheitsklasse: -; Sonnenschutztyp: Movable; g-Wert: 0,51
 | H2 Ebene +1 | WA-LB | 1155Wa 0000200045 | yes | Codetext | m² | Trockenbauarbeiten | Wand | Außenwand 7-Schalig | WA-LB | 0 | A | 3.75 | 1155HWa0000199934 | NEW | no | yes | 0 | 0.9 | no | 32 | no | Codetext | AllplanAttributes - ash D_Detailverweis: PL 1850; Sicherheitsklasse: -; Sonnenschutztyp: Movable; g-Wert: 0,51
 | H2 Ebene +1 | WA-KL | 1155Wa 0000200044 | yes | Codetext | m² | Zimmer- und Holzbauarbeiten | Wand | Außenwand 7-Schalig | WA-KL | 0 | A | 3.75 | 1155HWa0000199934 | NEW | no | yes | 0 | 0.9 | no | 32 | no | Codetext | AllplanAttributes - ash D_Detailverweis: PL 1850; Sicherheitsklasse: -; Sonnenschutztyp: Movable; g-Wert: 0,51
 | H2 Ebene +1 | WA-TL | 1155Wa 0000200043 | yes | Codetext | m² | Zimmer- und Holzbauarbeiten | Wand | Außenwand 7-Schalig | WA-TL | 0 | A | 3.75 | 1155HWa0000199934 | NEW | no | yes | 0 | 0.9 | no | 32 | no | Codetext | AllplanAttributes - ash D_Detailverweis: PL 1850; Sicherheitsklasse: -; Sonnenschutztyp: Movable; g-Wert: 0,51
 | H2 Ebene +1 | WA-HS | 1155Wa 0000200042 | yes | Codetext | m² | Zimmer- und Holzbauarbeiten | Wand | Außenwand 7-Schalig | WA-HS | 0 | A | 3.75 | 1155HWa0000199934 | NEW | no | yes | 0 | 0.9 | no | 32 | no | Codetext | AllplanAttributes - ash D_Detailverweis: PL 1850; Sicherheitsklasse: -; Sonnenschutztyp: Movable; g-Wert: 0,51
 | H2 Ebene +1 | WA-LB | 1155Wa 0813749812 | yes | Codetext | m² | Trockenbauarbeiten | Wand | Außenwand 7-Schalig | WA-LB | 0 | A | 3.75 | 1155HWa0000197205 | NEW | no | yes | 0 | 0.9 | no | 32 | no | Codetext | AllplanAttributes - Sicherheitsklasse: -; Sonnenschutztyp: Movable; g-Wert: 0,51
 | H2 Ebene +1 | WA-HD | 1155Wa 0813749813 | yes | Codetext | m³ | Zimmer- und Holzbauarbeiten | Wand | Außenwand 7-Schalig | WA-HD | 0 | A | 3.75 | 1155HWa0000197205 | NEW | no | yes | 0 | 0.9 | no | 32 | no | Codetext | AllplanAttributes - Sicherheitsklasse: -; Sonnenschutztyp: Movable; g-Wert: 0,51; ash W_laufende Nr. Statik: 2 (W 2.0/ 2.1/ 2.2)
 | H2 Ebene +1 | WA-DL | 1155Wa 0813749814 | yes | Codetext | m³ | Zimmer- und Holzbauarbeiten | Wand | Außenwand 7-Schalig | WA-DL | 0 | A | 3.75 | 1155HWa0000197205 | NEW | no | yes | 0 | 0.9 | no | 32 | no | Codetext | AllplanAttributes - Sicherheitsklasse: -; Sonnenschutztyp: Movable; g-Wert: 0,51
 | H2 Ebene +1 | WA-LB | 1155Wa 0813749815 | yes | Codetext | m² | Trockenbauarbeiten | Wand | Außenwand 7-Schalig | WA-LB | 0 | A | 3.75 | 1155HWa0000197205 | NEW | no | yes | 0 | 0.9 | no | 32 | no | Codetext | AllplanAttributes - Sicherheitsklasse: -; Sonnenschutztyp: Movable; g-Wert: 0,51
 | H2 Ebene +1 | WA-KL | 1155Wa 0813749816 | yes | Codetext | m² | Zimmer- und Holzbauarbeiten | Wand | Außenwand 7-Schalig | WA-KL | 0 | A | 3.75 | 1155HWa0000197205 | NEW | no | yes | 0 | 0.9 | no | 32 | no | Codetext | AllplanAttributes - Sicherheitsklasse: -; Sonnenschutztyp: Movable; g-Wert: 0,51
 | H2 Ebene +1 | WA-TL | 1155Wa 0813749817 | yes | Codetext | m² | Zimmer- und Holzbauarbeiten | Wand | Außenwand 7-Schalig | WA-TL | 0 | A | 3.75 | 1155HWa0000197205 | NEW | no | yes | 0 | 0.9 | no | 32 | no | Codetext | AllplanAttributes - Sicherheitsklasse: -; Sonnenschutztyp: Movable; g-Wert: 0,51
 | H2 Ebene +1 | WA-HS | 1155Wa 0813749818 | yes | Codetext | m² | Zimmer- und Holzbauarbeiten | Wand | Außenwand 7-Schalig | WA-HS | 0 | A | 3.75 | 1155HWa0000197205 | NEW | no | yes | 0 | 0.9 | no | 32 | no | Codetext | AllplanAttributes - Sicherheitsklasse: -; Sonnenschutztyp: Movable; g-Wert: 0,51
 | H2 Ebene +1 | WA-LB | 1155Wa 0000001868 | yes | Codetext | m² | Trockenbauarbeiten | Wand | Außenwand 7-Schalig | WA-LB | 0 | A | 3.75 | 1155HWa0000000198 | NEW | no | yes | 0 | 0.9 | no | 32 | no | Codetext | AllplanAttributes - Sicherheitsklasse: -; Sonnenschutztyp: Movable; g-Wert: 0,51
 | H2 Ebene +1 | WA-HD | 1155Wa 0000001872 | yes | Codetext | m³ | Zimmer- und Holzbauarbeiten | Wand | Außenwand 7-Schalig | WA-HD | 0 | A | 3.75 | 1155HWa0000000198 | NEW | no | yes | 0 | 0.9 | no | 32 | no | Codetext | AllplanAttributes - ash D_Detailverweis: DT C; ash D_Plannummer: D1851; Sicherheitsklasse: -; Sonnenschutztyp: Movable; g-Wert: 0,51; ash W_laufende Nr. Statik: 2 (W 2.0/ 2.1/ 2.2)
 | H2 Ebene +1 | WA-DL | 1155Wa 0000001876 | yes | Codetext | m³ | Zimmer- und Holzbauarbeiten | Wand | Außenwand 7-Schalig | WA-DL | 0 | A | 3.75 | 1155HWa0000000198 | NEW | no | yes | 0 | 0.9 | no | 32 | no | Codetext | AllplanAttributes - Sicherheitsklasse: -; Sonnenschutztyp: Movable; g-Wert: 0,51
 | H2 Ebene +1 | WA-LB | 1155Wa 0000001880 | yes | Codetext | m² | Trockenbauarbeiten | Wand | Außenwand 7-Schalig | WA-LB | 0 | A | 3.75 | 1155HWa0000000198 | NEW | no | yes | 0 | 0.9 | no | 32 | no | Codetext | AllplanAttributes - Sicherheitsklasse: -; Sonnenschutztyp: Movable; g-Wert: 0,51
 | H2 Ebene +1 | WA-KL | 1155Wa 0000001884 | yes | Codetext | m² | Zimmer- und Holzbauarbeiten | Wand | Außenwand 7-Schalig | WA-KL | 0 | A | 3.75 | 1155HWa0000000198 | NEW | no | yes | 0 | 0.9 | no | 32 | no | Codetext | AllplanAttributes - Sicherheitsklasse: -; Sonnenschutztyp: Movable; g-Wert: 0,51
 | H2 Ebene +1 | WA-TL | 1155Wa 0000001888 | yes | Codetext | m² | Zimmer- und Holzbauarbeiten | Wand | Außenwand 7-Schalig | WA-TL | 0 | A | 3.75 | 1155HWa0000000198 | NEW | no | yes | 0 | 0.9 | no | 32 | no | Codetext | AllplanAttributes - Sicherheitsklasse: -; Sonnenschutztyp: Movable; g-Wert: 0,51
 | H2 Ebene +1 | WA-HS | 1155Wa 0000001892 | yes | Codetext | m² | Zimmer- und Holzbauarbeiten | Wand | Außenwand 7-Schalig | WA-HS | 0 | A | 3.75 | 1155HWa0000000198 | NEW | no | yes | 0 | 0.9 | no | 32 | no | Codetext | AllplanAttributes - Sicherheitsklasse: -; Sonnenschutztyp: Movable; g-Wert: 0,51
2x Gipsfaserplatte | H2 Ebene +1 | WA-LB | 1155Wa 0000200218 | yes |  | m² | Trockenbauarbeiten | Wand | 2x Gipsfaserplatte | WA-LB |  |  | 3.75 | 1155HWa0000200208 | NEW | no | yes | 0 | 0.9 |  | 32 | AllplanAttributes - ash D_Detailverweis: D1850; Sicherheitsklasse: -; Sonnenschutztyp: Movable; g-Wert: 0,51
2x Gipsfaserplatte | H2 Ebene +1 | WA-LB | 1155Wa 0000200217 | yes |  | m² | Trockenbauarbeiten | Wand | 2x Gipsfaserplatte | WA-LB |  |  | 3.75 | 1155HWa0000200208 | NEW | no | yes | 0 | 0.9 |  | 32 | AllplanAttributes - ash D_Detailverweis: D1850; Sicherheitsklasse: -; Sonnenschutztyp: Movable; g-Wert: 0,51
Holzständer + Zwischendämmung | H2 Ebene +1 | WA-DL | 1155Wa 0000200216 | yes |  | m³ | Zimmer- und Holzbauarbeiten | Wand | Holzständer + Zwischendämmung | WA-DL |  |  | 3.75 | 1155HWa0000200208 | NEW | no | yes | 0 | 0.9 |  | 32 | AllplanAttributes - ash D_Detailverweis: DT A; ash D_Plannummer: D1850; Sicherheitsklasse: -; Sonnenschutztyp: Movable; g-Wert: 0,51; ash W_laufende Nr. Statik: 6 (W 6.0)
 | H2 Ebene +1 | WA-LB | 1155Wa 0000200215 | yes | Codetext | m² | Trockenbauarbeiten | Wand | Außenwand 7-Schalig | WA-LB | 0 | A | 3.75 | 1155HWa0000200208 | NEW | no | yes | 0 | 0.9 | no | 32 | no | Codetext | AllplanAttributes - ash D_Detailverweis: D1850; Sicherheitsklasse: -; Sonnenschutztyp: Movable; g-Wert: 0,51
 | H2 Ebene +1 | WA-LB | 1155Wa 0000200214 | yes | Codetext | m² | Trockenbauarbeiten | Wand | Außenwand 7-Schalig | WA-LB | 0 | A | 3.75 | 1155HWa0000200208 | NEW | no | yes | 0 | 0.9 | no | 32 | no | Codetext | AllplanAttributes - ash D_Detailverweis: D1850; Sicherheitsklasse: -; Sonnenschutztyp: Movable; g-Wert: 0,51
Staffel + Zwischendämmung | H2 Ebene +1 | WA-DL | 1155Wa 0000200213 | yes |  | m³ | Zimmer- und Holzbauarbeiten | Wand | Staffel + Zwischendämmung | WA-DL |  |  | 3.75 | 1155HWa0000200208 | NEW | no | yes | 0 | 0.9 |  | 32 | AllplanAttributes - ash D_Detailverweis: D1850; Sicherheitsklasse: -; Sonnenschutztyp: Movable; g-Wert: 0,51
Konterlattung | H2 Ebene +1 | WA-KL | 1155Wa 0000200212 | yes |  | m² | Zimmer- und Holzbauarbeiten | Wand | Konterlattung | WA-KL |  |  | 3.75 | 1155HWa0000200208 | NEW | no | yes | 0 | 0.9 |  | 32 | AllplanAttributes - ash D_Detailverweis: D1850; Sicherheitsklasse: -; Sonnenschutztyp: Movable; g-Wert: 0,51
Traglattung | H2 Ebene +1 | WA-TL | 1155Wa 0000200211 | yes |  | m² | Zimmer- und Holzbauarbeiten | Wand | Traglattung | WA-TL |  |  | 3.75 | 1155HWa0000200208 | NEW | no | yes | 0 | 0.9 |  | 32 | AllplanAttributes - ash D_Detailverweis: D1850; Sicherheitsklasse: -; Sonnenschutztyp: Movable; g-Wert: 0,51
Keramikschindel | H2 Ebene +1 | WA-HS | 1155Wa 0000200210 | yes |  | m² | Zimmer- und Holzbauarbeiten | Wand | Keramikschindel | WA-HS |  |  | 3.75 | 1155HWa0000200208 | NEW | no | yes | 0 | 0.9 |  | 32 | AllplanAttributes - ash D_Detailverweis: D1850; Sicherheitsklasse: -; Sonnenschutztyp: Movable; g-Wert: 0,51
 | H2 Ebene +1 | WA-LB | 1155Wa 0000002821 | yes | Codetext | m² | Trockenbauarbeiten | Wand | Außenwand 7-Schalig | WA-LB | 0 | A | 3.75 | 1155HWa0000002753 | NEW | no | yes | 0 | 0.9 | no | 32 | no | Codetext | AllplanAttributes - Sicherheitsklasse: -; Sonnenschutztyp: Movable; g-Wert: 0,51
 | H2 Ebene +1 | WA-HD | 1155Wa 0000002819 | yes | Codetext | m³ | Zimmer- und Holzbauarbeiten | Wand | Außenwand 7-Schalig | WA-HD | 0 | A | 3.75 | 1155HWa0000002753 | NEW | no | yes | 0 | 0.9 | no | 32 | no | Codetext | AllplanAttributes - ash D_Detailverweis: DT B; ash D_Plannummer: D1851; Sicherheitsklasse: -; Sonnenschutztyp: Movable; g-Wert: 0,51
 | H2 Ebene +1 | WA-DL | 1155Wa 0000002817 | yes | Codetext | m³ | Zimmer- und Holzbauarbeiten | Wand | Außenwand 7-Schalig | WA-DL | 0 | A | 3.75 | 1155HWa0000002753 | NEW | no | yes | 0 | 0.9 | no | 32 | no | Codetext | AllplanAttributes - Sicherheitsklasse: -; Sonnenschutztyp: Movable; g-Wert: 0,51
 | H2 Ebene +1 | WA-LB | 1155Wa 0000002815 | yes | Codetext | m² | Trockenbauarbeiten | Wand | Außenwand 7-Schalig | WA-LB | 0 | A | 3.75 | 1155HWa0000002753 | NEW | no | yes | 0 | 0.9 | no | 32 | no | Codetext | AllplanAttributes - Sicherheitsklasse: -; Sonnenschutztyp: Movable; g-Wert: 0,51
 | H2 Ebene +1 | WA-KL | 1155Wa 0000002813 | yes | Codetext | m² | Zimmer- und Holzbauarbeiten | Wand | Außenwand 7-Schalig | WA-KL | 0 | A | 3.75 | 1155HWa0000002753 | NEW | no | yes | 0 | 0.9 | no | 32 | no | Codetext | AllplanAttributes - Sicherheitsklasse: -; Sonnenschutztyp: Movable; g-Wert: 0,51
 | H2 Ebene +1 | WA-TL | 1155Wa 0000002811 | yes | Codetext | m² | Zimmer- und Holzbauarbeiten | Wand | Außenwand 7-Schalig | WA-TL | 0 | A | 3.75 | 1155HWa0000002753 | NEW | no | yes | 0 | 0.9 | no | 32 | no | Codetext | AllplanAttributes - Sicherheitsklasse: -; Sonnenschutztyp: Movable; g-Wert: 0,51
 | H2 Ebene +1 | WA-HS | 1155Wa 0000002809 | yes | Codetext | m² | Zimmer- und Holzbauarbeiten | Wand | Außenwand 7-Schalig | WA-HS | 0 | A | 3.75 | 1155HWa0000002753 | NEW | no | yes | 0 | 0.9 | no | 32 | no | Codetext | AllplanAttributes - Sicherheitsklasse: -; Sonnenschutztyp: Movable; g-Wert: 0,51
 | H2 Ebene +1 | WA-LB | 1155Wa 0000002676 | yes | Codetext | m² | Trockenbauarbeiten | Wand | Außenwand 7-Schalig | WA-LB | 0 | A | 3.75 | 1155HWa0000002426 | NEW | no | yes | 0 | 0.9 | no | 32 | no | Codetext | AllplanAttributes - Sicherheitsklasse: -; Sonnenschutztyp: Movable; g-Wert: 0,51
 | H2 Ebene +1 | WA-HD | 1155Wa 0000002672 | yes | Codetext | m³ | Zimmer- und Holzbauarbeiten | Wand | Außenwand 7-Schalig | WA-HD | 0 | A | 3.75 | 1155HWa0000002426 | NEW | no | yes | 0 | 0.9 | no | 32 | no | Codetext | AllplanAttributes - ash D_Detailverweis: DT C/D; ash D_Plannummer: D1851; Sicherheitsklasse: -; Sonnenschutztyp: Movable; g-Wert: 0,51; ash W_laufende Nr. Statik: 5 (W 4.0)
 | H2 Ebene +1 | WA-DL | 1155Wa 0000002668 | yes | Codetext | m³ | Zimmer- und Holzbauarbeiten | Wand | Außenwand 7-Schalig | WA-DL | 0 | A | 3.75 | 1155HWa0000002426 | NEW | no | yes | 0 | 0.9 | no | 32 | no | Codetext | AllplanAttributes - Sicherheitsklasse: -; Sonnenschutztyp: Movable; g-Wert: 0,51
 | H2 Ebene +1 | WA-LB | 1155Wa 0000002664 | yes | Codetext | m² | Trockenbauarbeiten | Wand | Außenwand 7-Schalig | WA-LB | 0 | A | 3.75 | 1155HWa0000002426 | NEW | no | yes | 0 | 0.9 | no | 32 | no | Codetext | AllplanAttributes - Sicherheitsklasse: -; Sonnenschutztyp: Movable; g-Wert: 0,51
 | H2 Ebene +1 | WA-KL | 1155Wa 0000002660 | yes | Codetext | m² | Zimmer- und Holzbauarbeiten | Wand | Außenwand 7-Schalig | WA-KL | 0 | A | 3.75 | 1155HWa0000002426 | NEW | no | yes | 0 | 0.9 | no | 32 | no | Codetext | AllplanAttributes - Sicherheitsklasse: -; Sonnenschutztyp: Movable; g-Wert: 0,51
 | H2 Ebene +1 | WA-TL | 1155Wa 0000002656 | yes | Codetext | m² | Zimmer- und Holzbauarbeiten | Wand | Außenwand 7-Schalig | WA-TL | 0 | A | 3.75 | 1155HWa0000002426 | NEW | no | yes | 0 | 0.9 | no | 32 | no | Codetext | AllplanAttributes - Sicherheitsklasse: -; Sonnenschutztyp: Movable; g-Wert: 0,51
Keramikschindel | H2 Ebene +1 | WA-HS | 1155Wa 0000002652 | yes | Codetext | m² | Zimmer- und Holzbauarbeiten | Wand | Keramikschindel | WA-HS | 0 | A | 3.75 | 1155HWa0000002426 | NEW | no | yes | 0 | 0.9 | no | 32 | no | Codetext | AllplanAttributes - Sicherheitsklasse: -; Sonnenschutztyp: Movable; g-Wert: 0,51
 | H2 Ebene +1 | WA-LB | 1155Wa 0000002699 | yes | Codetext | m² | Trockenbauarbeiten | Wand | Außenwand 7-Schalig | WA-LB | 0 | A | 3.75 | 1155HWa0000002199 | NEW | no | yes | 0 | 0.9 | no | 32 | no | Codetext | AllplanAttributes - Sicherheitsklasse: -; Sonnenschutztyp: Movable; g-Wert: 0,51
 | H2 Ebene +1 | WA-HD | 1155Wa 0000002706 | yes | Codetext | m³ | Zimmer- und Holzbauarbeiten | Wand | Außenwand 7-Schalig | WA-HD | 0 | A | 3.75 | 1155HWa0000002199 | NEW | no | yes | 0 | 0.9 | no | 32 | no | Codetext | AllplanAttributes - ash D_Detailverweis: DT C; ash D_Plannummer: D1851; Sicherheitsklasse: -; Sonnenschutztyp: Movable; g-Wert: 0,51; ash W_laufende Nr. Statik: 2 (W 2.0/ 2.1/ 2.2)
 | H2 Ebene +1 | WA-DL | 1155Wa 0000002713 | yes | Codetext | m³ | Zimmer- und Holzbauarbeiten | Wand | Außenwand 7-Schalig | WA-DL | 0 | A | 3.75 | 1155HWa0000002199 | NEW | no | yes | 0 | 0.9 | no | 32 | no | Codetext | AllplanAttributes - Sicherheitsklasse: -; Sonnenschutztyp: Movable; g-Wert: 0,51
 | H2 Ebene +1 | WA-LB | 1155Wa 0000002720 | yes | Codetext | m² | Trockenbauarbeiten | Wand | Außenwand 7-Schalig | WA-LB | 0 | A | 3.75 | 1155HWa0000002199 | NEW | no | yes | 0 | 0.9 | no | 32 | no | Codetext | AllplanAttributes - Sicherheitsklasse: -; Sonnenschutztyp: Movable; g-Wert: 0,51
 | H2 Ebene +1 | WA-KL | 1155Wa 0000002727 | yes | Codetext | m² | Zimmer- und Holzbauarbeiten | Wand | Außenwand 7-Schalig | WA-KL | 0 | A | 3.75 | 1155HWa0000002199 | NEW | no | yes | 0 | 0.9 | no | 32 | no | Codetext | AllplanAttributes - Sicherheitsklasse: -; Sonnenschutztyp: Movable; g-Wert: 0,51
 | H2 Ebene +1 | WA-TL | 1155Wa 0000002734 | yes | Codetext | m² | Zimmer- und Holzbauarbeiten | Wand | Außenwand 7-Schalig | WA-TL | 0 | A | 3.75 | 1155HWa0000002199 | NEW | no | yes | 0 | 0.9 | no | 32 | no | Codetext | AllplanAttributes - Sicherheitsklasse: -; Sonnenschutztyp: Movable; g-Wert: 0,51
 | H2 Ebene +1 | WA-HS | 1155Wa 0000002741 | yes | Codetext | m² | Zimmer- und Holzbauarbeiten | Wand | Außenwand 7-Schalig | WA-HS | 0 | A | 3.75 | 1155HWa0000002199 | NEW | no | yes | 0 | 0.9 | no | 32 | no | Codetext | AllplanAttributes - Sicherheitsklasse: -; Sonnenschutztyp: Movable; g-Wert: 0,51
2x Gipsfaserplatte | H2 Ebene +1 | WA-LB | 1155Wa 0813746110 | yes |  | m² | Trockenbauarbeiten | Wand | 2x Gipsfaserplatte | WA-LB |  |  | 3.75 | 1155HWa0000193601 | NEW | no | yes | 0 | 0.9 |  | 32 | AllplanAttributes - Sicherheitsklasse: -; Sonnenschutztyp: Movable; g-Wert: 0,51
2x Gipsfaserplatte | H2 Ebene +1 | WA-LB | 1155Wa 0813746109 | yes |  | m² | Trockenbauarbeiten | Wand | 2x Gipsfaserplatte | WA-LB |  |  | 3.75 | 1155HWa0000193601 | NEW | no | yes | 0 | 0.9 |  | 32 | AllplanAttributes - Sicherheitsklasse: -; Sonnenschutztyp: Movable; g-Wert: 0,51
Holzständer + Zwischendämmung | H2 Ebene +1 | WA-DL | 1155Wa 0813746108 | yes |  | m³ | Zimmer- und Holzbauarbeiten | Wand | Holzständer + Zwischendämmung | WA-DL |  |  | 3.75 | 1155HWa0000193601 | NEW | no | yes | 0 | 0.9 |  | 32 | AllplanAttributes - ash D_Detailverweis: DT F; ash D_Plannummer: D1851; Sicherheitsklasse: -; Sonnenschutztyp: Movable; g-Wert: 0,51; ash W_laufende Nr. Statik: 6 (W 6.0)
 | H2 Ebene +1 | WA-LB | 1155Wa 0813746107 | yes | Codetext | m² | Trockenbauarbeiten | Wand | Außenwand 7-Schalig | WA-LB | 0 | A | 3.75 | 1155HWa0000193601 | NEW | no | yes | 0 | 0.9 | no | 32 | no | Codetext | AllplanAttributes - Sicherheitsklasse: -; Sonnenschutztyp: Movable; g-Wert: 0,51
 | H2 Ebene +1 | WA-LB | 1155Wa 0813746106 | yes | Codetext | m² | Trockenbauarbeiten | Wand | Außenwand 7-Schalig | WA-LB | 0 | A | 3.75 | 1155HWa0000193601 | NEW | no | yes | 0 | 0.9 | no | 32 | no | Codetext | AllplanAttributes - Sicherheitsklasse: -; Sonnenschutztyp: Movable; g-Wert: 0,51
Staffel + Zwischendämmung | H2 Ebene +1 | WA-DL | 1155Wa 0813746105 | yes |  | m³ | Zimmer- und Holzbauarbeiten | Wand | Staffel + Zwischendämmung | WA-DL |  |  | 3.75 | 1155HWa0000193601 | NEW | no | yes | 0 | 0.9 |  | 32 | AllplanAttributes - Sicherheitsklasse: -; Sonnenschutztyp: Movable; g-Wert: 0,51
Konterlattung | H2 Ebene +1 | WA-KL | 1155Wa 0813746104 | yes |  | m² | Zimmer- und Holzbauarbeiten | Wand | Konterlattung | WA-KL |  |  | 3.75 | 1155HWa0000193601 | NEW | no | yes | 0 | 0.9 |  | 32 | AllplanAttributes - Sicherheitsklasse: -; Sonnenschutztyp: Movable; g-Wert: 0,51
Traglattung | H2 Ebene +1 | WA-TL | 1155Wa 0813746103 | yes |  | m² | Zimmer- und Holzbauarbeiten | Wand | Traglattung | WA-TL |  |  | 3.75 | 1155HWa0000193601 | NEW | no | yes | 0 | 0.9 |  | 32 | AllplanAttributes - Sicherheitsklasse: -; Sonnenschutztyp: Movable; g-Wert: 0,51
Keramikschindel | H2 Ebene +1 | WA-HS | 1155Wa 0813746102 | yes |  | m² | Zimmer- und Holzbauarbeiten | Wand | Keramikschindel | WA-HS |  |  | 3.75 | 1155HWa0000193601 | NEW | no | yes | 0 | 0.9 |  | 32 | AllplanAttributes - Sicherheitsklasse: -; Sonnenschutztyp: Movable; g-Wert: 0,51
 | H2 Ebene +1 | WA-LB | 1155Wa 0000191477 | yes | Codetext | m² | Trockenbauarbeiten | Wand | Außenwand 7-Schalig | WA-LB | 0 | A | 3.75 | 1155HWa0000191369 | NEW | no | yes | 0 | 0.9 | no | 32 | no | Codetext | AllplanAttributes - Sicherheitsklasse: -; Sonnenschutztyp: Movable; g-Wert: 0,51
 | H2 Ebene +1 | WA-HD | 1155Wa 0000191478 | yes | Codetext | m³ | Zimmer- und Holzbauarbeiten | Wand | Außenwand 7-Schalig | WA-HD | 0 | A | 3.75 | 1155HWa0000191369 | NEW | no | yes | 0 | 0.9 | no | 32 | no | Codetext | AllplanAttributes - Sicherheitsklasse: -; Sonnenschutztyp: Movable; g-Wert: 0,51; ash W_laufende Nr. Statik: 2 (W 2.0/ 2.1/ 2.2)
 | H2 Ebene +1 | WA-DL | 1155Wa 0000191479 | yes | Codetext | m³ | Zimmer- und Holzbauarbeiten | Wand | Außenwand 7-Schalig | WA-DL | 0 | A | 3.75 | 1155HWa0000191369 | NEW | no | yes | 0 | 0.9 | no | 32 | no | Codetext | AllplanAttributes - Sicherheitsklasse: -; Sonnenschutztyp: Movable; g-Wert: 0,51
 | H2 Ebene +1 | WA-LB | 1155Wa 0000191480 | yes | Codetext | m² | Trockenbauarbeiten | Wand | Außenwand 7-Schalig | WA-LB | 0 | A | 3.75 | 1155HWa0000191369 | NEW | no | yes | 0 | 0.9 | no | 32 | no | Codetext | AllplanAttributes - Sicherheitsklasse: -; Sonnenschutztyp: Movable; g-Wert: 0,51
 | H2 Ebene +1 | WA-KL | 1155Wa 0000191481 | yes | Codetext | m² | Zimmer- und Holzbauarbeiten | Wand | Außenwand 7-Schalig | WA-KL | 0 | A | 3.75 | 1155HWa0000191369 | NEW | no | yes | 0 | 0.9 | no | 32 | no | Codetext | AllplanAttributes - Sicherheitsklasse: -; Sonnenschutztyp: Movable; g-Wert: 0,51
 | H2 Ebene +1 | WA-TL | 1155Wa 0000191482 | yes | Codetext | m² | Zimmer- und Holzbauarbeiten | Wand | Außenwand 7-Schalig | WA-TL | 0 | A | 3.75 | 1155HWa0000191369 | NEW | no | yes | 0 | 0.9 | no | 32 | no | Codetext | AllplanAttributes - Sicherheitsklasse: -; Sonnenschutztyp: Movable; g-Wert: 0,51
 | H2 Ebene +1 | WA-HS | 1155Wa 0000191483 | yes | Codetext | m² | Zimmer- und Holzbauarbeiten | Wand | Außenwand 7-Schalig | WA-HS | 0 | A | 3.75 | 1155HWa0000191369 | NEW | no | yes | 0 | 0.9 | no | 32 | no | Codetext | AllplanAttributes - ash D_Detailverweis: FS13; ash D_Plannummer: D1854; Sicherheitsklasse: -; Sonnenschutztyp: Movable; g-Wert: 0,51
 | H2 Ebene +1 | WA-LB | 1155Wa 0000001093 | yes | Codetext | m² | Trockenbauarbeiten | Wand | Außenwand 7-Schalig | WA-LB | 0 | A | 3.75 | 1155HWa0000000994 | NEW | no | yes | 0 | 0.9 | no | 32 | no | Codetext | AllplanAttributes - Sicherheitsklasse: -; Sonnenschutztyp: Movable; g-Wert: 0,51
 | H2 Ebene +1 | WA-HD | 1155Wa 0000001097 | yes | Codetext | m³ | Zimmer- und Holzbauarbeiten | Wand | Außenwand 7-Schalig | WA-HD | 0 | A | 3.75 | 1155HWa0000000994 | NEW | no | yes | 0 | 0.9 | no | 32 | no | Codetext | AllplanAttributes - Sicherheitsklasse: -; Sonnenschutztyp: Movable; g-Wert: 0,51; ash W_laufende Nr. Statik: 2 (W 2.0/ 2.1/ 2.2)
 | H2 Ebene +1 | WA-DL | 1155Wa 0000001117 | yes | Codetext | m³ | Zimmer- und Holzbauarbeiten | Wand | Außenwand 7-Schalig | WA-DL | 0 | A | 3.75 | 1155HWa0000000994 | NEW | no | yes | 0 | 0.9 | no | 32 | no | Codetext | AllplanAttributes - Sicherheitsklasse: -; Sonnenschutztyp: Movable; g-Wert: 0,51
 | H2 Ebene +1 | WA-LB | 1155Wa 0000001113 | yes | Codetext | m² | Trockenbauarbeiten | Wand | Außenwand 7-Schalig | WA-LB | 0 | A | 3.75 | 1155HWa0000000994 | NEW | no | yes | 0 | 0.9 | no | 32 | no | Codetext | AllplanAttributes - Sicherheitsklasse: -; Sonnenschutztyp: Movable; g-Wert: 0,51
 | H2 Ebene +1 | WA-KL | 1155Wa 0000001109 | yes | Codetext | m² | Zimmer- und Holzbauarbeiten | Wand | Außenwand 7-Schalig | WA-KL | 0 | A | 3.75 | 1155HWa0000000994 | NEW | no | yes | 0 | 0.9 | no | 32 | no | Codetext | AllplanAttributes - Sicherheitsklasse: -; Sonnenschutztyp: Movable; g-Wert: 0,51
 | H2 Ebene +1 | WA-TL | 1155Wa 0000001105 | yes | Codetext | m² | Zimmer- und Holzbauarbeiten | Wand | Außenwand 7-Schalig | WA-TL | 0 | A | 3.75 | 1155HWa0000000994 | NEW | no | yes | 0 | 0.9 | no | 32 | no | Codetext | AllplanAttributes - Sicherheitsklasse: -; Sonnenschutztyp: Movable; g-Wert: 0,51
 | H2 Ebene +1 | WA-HS | 1155Wa 0000001101 | yes | Codetext | m² | Zimmer- und Holzbauarbeiten | Wand | Außenwand 7-Schalig | WA-HS | 0 | A | 3.75 | 1155HWa0000000994 | NEW | no | yes | 0 | 0.9 | no | 32 | no | Codetext | AllplanAttributes - ash D_Detailverweis: FS 2; ash D_Plannummer: D781; Sicherheitsklasse: -; Sonnenschutztyp: Movable; g-Wert: 0,51
 | H2 Ebene +1 | WA-FAS | 1155Wa 2005678957 | yes | Codetext | m² | Vorgehängte Fassaden | Wand | Außenwand mehrschalig | WA-FAS | 0 | A |  | 1106HWa0000000475 | NEW | no | yes | 0 | 0 | no | 0 | no | Codetext
 | H2 Ebene +1 | WA-FAS | 1155Wa 2005678958 | yes | Codetext | m² | Vorgehängte Fassaden | Wand | Außenwand mehrschalig | WA-FAS | 0 | A |  | 1106HWa0000000475 | NEW | no | yes | 0 | 0 | no | 0 | no | Codetext
 | H2 Ebene +1 | WA-FAS | 1155Wa 2005680082 | yes | Codetext | m² | Vorgehängte Fassaden | Wand | Außenwand mehrschalig | WA-FAS | 0 | A |  | 1106HWa0000000475 | NEW | no | yes | 0 | 0 | no | 0 | no | Codetext
 | H2 Ebene +1 | WA-FAS | 1155Wa 2005680081 | yes | Codetext | m² | Vorgehängte Fassaden | Wand | Außenwand mehrschalig | WA-FAS | 0 | A |  | 1106HWa0000000475 | NEW | no | yes | 0 | 0 | no | 0 | no | Codetext
 | H2 Ebene +1 | WA-LB | 1155Wa 0000121234 | yes | Codetext | m² | Trockenbauarbeiten | Wand | Außenwand 7-Schalig | WA-LB | 0 | A | 3.75 | 1155HWa0000121201 | NEW | no | yes | 0 | 0.9 | no | 32 | no | Codetext | AllplanAttributes - Sicherheitsklasse: -; Sonnenschutztyp: Movable; g-Wert: 0,51
 | H2 Ebene +1 | WA-HD | 1155Wa 0000121235 | yes | Codetext | m³ | Zimmer- und Holzbauarbeiten | Wand | Außenwand 7-Schalig | WA-HD | 0 | A | 3.75 | 1155HWa0000121201 | NEW | no | yes | 0 | 0.9 | no | 32 | no | Codetext | AllplanAttributes - Sicherheitsklasse: -; Sonnenschutztyp: Movable; g-Wert: 0,51; ash W_laufende Nr. Statik: 2 (W 2.0/ 2.1/ 2.2)
 | H2 Ebene +1 | WA-DL | 1155Wa 0000121240 | yes | Codetext | m³ | Zimmer- und Holzbauarbeiten | Wand | Außenwand 7-Schalig | WA-DL | 0 | A | 3.75 | 1155HWa0000121201 | NEW | no | yes | 0 | 0.9 | no | 32 | no | Codetext | AllplanAttributes - Sicherheitsklasse: -; Sonnenschutztyp: Movable; g-Wert: 0,51
 | H2 Ebene +1 | WA-LB | 1155Wa 0000121239 | yes | Codetext | m² | Trockenbauarbeiten | Wand | Außenwand 7-Schalig | WA-LB | 0 | A | 3.75 | 1155HWa0000121201 | NEW | no | yes | 0 | 0.9 | no | 32 | no | Codetext | AllplanAttributes - Sicherheitsklasse: -; Sonnenschutztyp: Movable; g-Wert: 0,51
 | H2 Ebene +1 | WA-KL | 1155Wa 0000121238 | yes | Codetext | m² | Zimmer- und Holzbauarbeiten | Wand | Außenwand 7-Schalig | WA-KL | 0 | A | 3.75 | 1155HWa0000121201 | NEW | no | yes | 0 | 0.9 | no | 32 | no | Codetext | AllplanAttributes - Sicherheitsklasse: -; Sonnenschutztyp: Movable; g-Wert: 0,51
 | H2 Ebene +1 | WA-TL | 1155Wa 0000121237 | yes | Codetext | m² | Zimmer- und Holzbauarbeiten | Wand | Außenwand 7-Schalig | WA-TL | 0 | A | 3.75 | 1155HWa0000121201 | NEW | no | yes | 0 | 0.9 | no | 32 | no | Codetext | AllplanAttributes - Sicherheitsklasse: -; Sonnenschutztyp: Movable; g-Wert: 0,51
 | H2 Ebene +1 | WA-HS | 1155Wa 0000121236 | yes | Codetext | m² | Zimmer- und Holzbauarbeiten | Wand | Außenwand 7-Schalig | WA-HS | 0 | A | 3.75 | 1155HWa0000121201 | NEW | no | yes | 0 | 0.9 | no | 32 | no | Codetext | AllplanAttributes - Sicherheitsklasse: -; Sonnenschutztyp: Movable; g-Wert: 0,51
 | H2 Ebene +1 | WA-LB | 1155Wa 2005699082 | yes | Codetext | m² | Trockenbauarbeiten | Wand | Außenwand 7-Schalig | WA-LB | 0 | A | 3.75 | 1155HWa0000000198 | NEW |  | yes | 0 | 0.9 | no | 32 | no | Codetext | AllplanAttributes - Sicherheitsklasse: -; Sonnenschutztyp: Movable; g-Wert: 0,51
 | H2 Ebene +1 | WA-HD | 1155Wa 2005699083 | yes | Codetext | m³ | Zimmer- und Holzbauarbeiten | Wand | Außenwand 7-Schalig | WA-HD | 0 | A | 3.75 | 1155HWa0000000198 | NEW |  | yes | 0 | 0.9 | no | 32 | no | Codetext | AllplanAttributes - ash D_Detailverweis: DT C; ash D_Plannummer: D1851; Sicherheitsklasse: -; Sonnenschutztyp: Movable; g-Wert: 0,51; ash W_laufende Nr. Statik: 2 (W 2.0/ 2.1/ 2.2)
 | H2 Ebene +1 | WA-DL | 1155Wa 2005699084 | yes | Codetext | m³ | Zimmer- und Holzbauarbeiten | Wand | Außenwand 7-Schalig | WA-DL | 0 | A | 3.75 | 1155HWa0000000198 | NEW |  | yes | 0 | 0.9 | no | 32 | no | Codetext | AllplanAttributes - Sicherheitsklasse: -; Sonnenschutztyp: Movable; g-Wert: 0,51
 | H2 Ebene +1 | WA-LB | 1155Wa 2005699085 | yes | Codetext | m² | Trockenbauarbeiten | Wand | Außenwand 7-Schalig | WA-LB | 0 | A | 3.75 | 1155HWa0000000198 | NEW |  | yes | 0 | 0.9 | no | 32 | no | Codetext | AllplanAttributes - Sicherheitsklasse: -; Sonnenschutztyp: Movable; g-Wert: 0,51
 | H2 Ebene +1 | WA-KL | 1155Wa 2005699086 | yes | Codetext | m² | Zimmer- und Holzbauarbeiten | Wand | Außenwand 7-Schalig | WA-KL | 0 | A | 3.75 | 1155HWa0000000198 | NEW |  | yes | 0 | 0.9 | no | 32 | no | Codetext | AllplanAttributes - Sicherheitsklasse: -; Sonnenschutztyp: Movable; g-Wert: 0,51
 | H2 Ebene +1 | WA-TL | 1155Wa 2005699087 | yes | Codetext | m² | Zimmer- und Holzbauarbeiten | Wand | Außenwand 7-Schalig | WA-TL | 0 | A | 3.75 | 1155HWa0000000198 | NEW |  | yes | 0 | 0.9 | no | 32 | no | Codetext | AllplanAttributes - Sicherheitsklasse: -; Sonnenschutztyp: Movable; g-Wert: 0,51
 | H2 Ebene +1 | WA-HS | 1155Wa 2005699088 | yes | Codetext | m² | Zimmer- und Holzbauarbeiten | Wand | Außenwand 7-Schalig | WA-HS | 0 | A | 3.75 | 1155HWa0000000198 | NEW |  | yes | 0 | 0.9 | no | 32 | no | Codetext | AllplanAttributes - Sicherheitsklasse: -; Sonnenschutztyp: Movable; g-Wert: 0,51
 | H2 Ebene +1 | WA-LB | 1155Wa 2005702249 | yes | Codetext | m² | Trockenbauarbeiten | Wand | Außenwand 7-Schalig | WA-LB | 0 | A | 3.75 | 1155HWa0000001726 | NEW | no | yes | 0 | 0.9 | no | 32 | no | Codetext | AllplanAttributes - Sicherheitsklasse: -; Sonnenschutztyp: Movable; g-Wert: 0,51
 | H2 Ebene +1 | WA-HD | 1155Wa 2005702250 | yes | Codetext | m³ | Zimmer- und Holzbauarbeiten | Wand | Außenwand 7-Schalig | WA-HD | 0 | A | 3.75 | 1155HWa0000001726 | NEW | no | yes | 0 | 0.9 | no | 32 | no | Codetext | AllplanAttributes - Sicherheitsklasse: -; Sonnenschutztyp: Movable; g-Wert: 0,51; ash W_laufende Nr. Statik: 5 (W 4.0)
 | H2 Ebene +1 | WA-DL | 1155Wa 2005702257 | yes | Codetext | m³ | Zimmer- und Holzbauarbeiten | Wand | Außenwand 7-Schalig | WA-DL | 0 | A | 3.75 | 1155HWa0000001726 | NEW | no | yes | 0 | 0.9 | no | 32 | no | Codetext | AllplanAttributes - Sicherheitsklasse: -; Sonnenschutztyp: Movable; g-Wert: 0,51
 | H2 Ebene +1 | WA-LB | 1155Wa 2005702256 | yes | Codetext | m² | Trockenbauarbeiten | Wand | Außenwand 7-Schalig | WA-LB | 0 | A | 3.75 | 1155HWa0000001726 | NEW | no | yes | 0 | 0.9 | no | 32 | no | Codetext | AllplanAttributes - Sicherheitsklasse: -; Sonnenschutztyp: Movable; g-Wert: 0,51
 | H2 Ebene +1 | WA-LB | 1155Wa 2005704467 | yes | Codetext | m² | Trockenbauarbeiten | Wand | Außenwand 7-Schalig | WA-LB | 0 | A | 3.75 | 1155HWa0000198179 | NEW | no | yes | 0 | 0.9 | no | 32 | no | Codetext | AllplanAttributes - Sicherheitsklasse: -; Sonnenschutztyp: Movable; g-Wert: 0,51
 | H2 Ebene +1 | WA-HD | 1155Wa 2005704468 | yes | Codetext | m³ | Zimmer- und Holzbauarbeiten | Wand | Außenwand 7-Schalig | WA-HD | 0 | A | 3.75 | 1155HWa0000198179 | NEW | no | yes | 0 | 0.9 | no | 32 | no | Codetext | AllplanAttributes - Sicherheitsklasse: -; Sonnenschutztyp: Movable; g-Wert: 0,51; ash W_laufende Nr. Statik: 5 (W 4.0)
 | H2 Ebene +1 | WA-DL | 1155Wa 2005704470 | yes | Codetext | m³ | Zimmer- und Holzbauarbeiten | Wand | Außenwand 7-Schalig | WA-DL | 0 | A | 3.75 | 1155HWa0000198179 | NEW | no | yes | 0 | 0.9 | no | 32 | no | Codetext | AllplanAttributes - Sicherheitsklasse: -; Sonnenschutztyp: Movable; g-Wert: 0,51
 | H2 Ebene +1 | WA-LB | 1155Wa 2005704469 | yes | Codetext | m² | Trockenbauarbeiten | Wand | Außenwand 7-Schalig | WA-LB | 0 | A | 3.75 | 1155HWa0000198179 | NEW | no | yes | 0 | 0.9 | no | 32 | no | Codetext | AllplanAttributes - Sicherheitsklasse: -; Sonnenschutztyp: Movable; g-Wert: 0,51
 | H2 Ebene +1 | WA-LB | 1155Wa 0000001193 | yes | Codetext | m² | Trockenbauarbeiten | Wand | Außenwand 7-Schalig | WA-LB | 0 | A | 3.75 | 1155HWa0000000998 | NEW | no | yes | 0 | 0.9 | no | 32 | no | Codetext | AllplanAttributes - Sicherheitsklasse: -; Sonnenschutztyp: Movable; g-Wert: 0,51
 | H2 Ebene +1 | WA-HD | 1155Wa 0000001197 | yes | Codetext | m³ | Zimmer- und Holzbauarbeiten | Wand | Außenwand 7-Schalig | WA-HD | 0 | A | 3.75 | 1155HWa0000000998 | NEW | no | yes | 0 | 0.9 | no | 32 | no | Codetext | AllplanAttributes - ash D_Detailverweis: DT C; ash D_Plannummer: D1851; Sicherheitsklasse: -; Sonnenschutztyp: Movable; g-Wert: 0,51; ash W_laufende Nr. Statik: 2 (W 2.0/ 2.1/ 2.2)
 | H2 Ebene +1 | WA-DL | 1155Wa 0000001201 | yes | Codetext | m³ | Zimmer- und Holzbauarbeiten | Wand | Außenwand 7-Schalig | WA-DL | 0 | A | 3.75 | 1155HWa0000000998 | NEW | no | yes | 0 | 0.9 | no | 32 | no | Codetext | AllplanAttributes - Sicherheitsklasse: -; Sonnenschutztyp: Movable; g-Wert: 0,51
 | H2 Ebene +1 | WA-LB | 1155Wa 0000001205 | yes | Codetext | m² | Trockenbauarbeiten | Wand | Außenwand 7-Schalig | WA-LB | 0 | A | 3.75 | 1155HWa0000000998 | NEW | no | yes | 0 | 0.9 | no | 32 | no | Codetext | AllplanAttributes - Sicherheitsklasse: -; Sonnenschutztyp: Movable; g-Wert: 0,51
 | H2 Ebene +1 | WA-KL | 1155Wa 0000001209 | yes | Codetext | m² | Zimmer- und Holzbauarbeiten | Wand | Außenwand 7-Schalig | WA-KL | 0 | A | 3.75 | 1155HWa0000000998 | NEW | no | yes | 0 | 0.9 | no | 32 | no | Codetext | AllplanAttributes - Sicherheitsklasse: -; Sonnenschutztyp: Movable; g-Wert: 0,51
 | H2 Ebene +1 | WA-TL | 1155Wa 0000001213 | yes | Codetext | m² | Zimmer- und Holzbauarbeiten | Wand | Außenwand 7-Schalig | WA-TL | 0 | A | 3.75 | 1155HWa0000000998 | NEW | no | yes | 0 | 0.9 | no | 32 | no | Codetext | AllplanAttributes - Sicherheitsklasse: -; Sonnenschutztyp: Movable; g-Wert: 0,51
 | H2 Ebene +1 | WA-HS | 1155Wa 0000001217 | yes | Codetext | m² | Zimmer- und Holzbauarbeiten | Wand | Außenwand 7-Schalig | WA-HS | 0 | A | 3.75 | 1155HWa0000000998 | NEW | no | yes | 0 | 0.9 | no | 32 | no | Codetext | AllplanAttributes - Sicherheitsklasse: -; Sonnenschutztyp: Movable; g-Wert: 0,51
2x Gipsfaserplatte | H2 Ebene +1 | WA-LB | 1155Wa 0000191884 | yes |  | m² | Trockenbauarbeiten | Wand | 2x Gipsfaserplatte | WA-LB |  |  | 3.75 | 1155HWa0000191819 | NEW | no | yes | 0 | 0.9 |  | 32 | AllplanAttributes - ash_W_Trockenbau_Qualitäten: 6; Sicherheitsklasse: -; Sonnenschutztyp: Movable; g-Wert: 0,51
2x Gipsfaserplatte | H2 Ebene +1 | WA-LB | 1155Wa 0000191883 | yes |  | m² | Trockenbauarbeiten | Wand | 2x Gipsfaserplatte | WA-LB |  |  | 3.75 | 1155HWa0000191819 | NEW | no | yes | 0 | 0.9 |  | 32 | AllplanAttributes - Sicherheitsklasse: -; Sonnenschutztyp: Movable; g-Wert: 0,51
Holzständer + Zwischendämmung | H2 Ebene +1 | WA-DL | 1155Wa 0000191882 | yes |  | m³ | Zimmer- und Holzbauarbeiten | Wand | Holzständer + Zwischendämmung | WA-DL |  |  | 3.75 | 1155HWa0000191819 | NEW | no | yes | 0 | 0.9 |  | 32 | AllplanAttributes - ash D_Detailverweis: DT F; ash D_Plannummer: D1851; Sicherheitsklasse: -; Sonnenschutztyp: Movable; g-Wert: 0,51; ash W_laufende Nr. Statik: 6 (W 6.0)
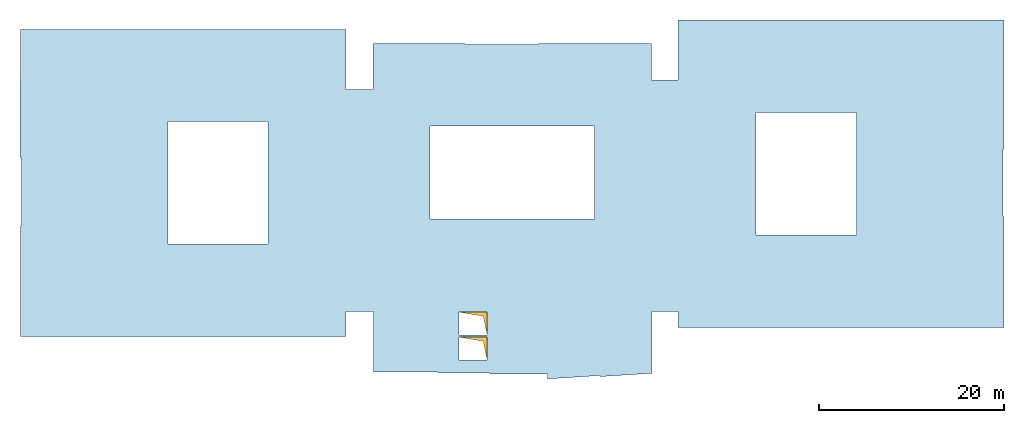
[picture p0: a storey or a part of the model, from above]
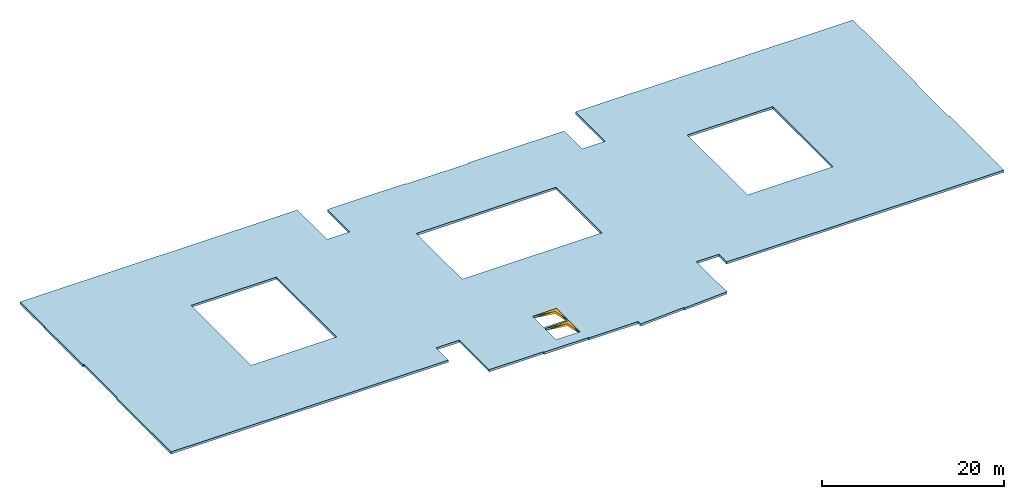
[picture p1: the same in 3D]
Properties of the parts of a building model (IFC4), part 62 of 80

# IfcWall (6826)
Name | In | Material | Allright_Bauteil_ID | 2D Interaktion | Codetext | Abrechnungsart | Gewerk | Objektname | Bezeichnung | AllplanAttributes, Material | Typ = SurfaceSpreadOfFlame | Brandschutzklasse | OKFF | P_ID | Status | LoadBearing | IsExternal | FireRating | ThermalTransmittance (W/K/m2) | Combustible | AcousticRating | Compartmentation | Reference
 | H2 Ebene +1 | WA-LB | 1155Wa 0000191881 | yes | Codetext | m² | Trockenbauarbeiten | Wand | Außenwand 7-Schalig | WA-LB | 0 | A | 3.75 | 1155HWa0000191819 | NEW | no | yes | 0 | 0.9 | no | 32 | no | Codetext | AllplanAttributes - Sicherheitsklasse: -; Sonnenschutztyp: Movable; g-Wert: 0,51
 | H2 Ebene +1 | WA-LB | 1155Wa 0000191880 | yes | Codetext | m² | Trockenbauarbeiten | Wand | Außenwand 7-Schalig | WA-LB | 0 | A | 3.75 | 1155HWa0000191819 | NEW | no | yes | 0 | 0.9 | no | 32 | no | Codetext | AllplanAttributes - Sicherheitsklasse: -; Sonnenschutztyp: Movable; g-Wert: 0,51
Staffel + Zwischendämmung | H2 Ebene +1 | WA-DL | 1155Wa 0000191879 | yes |  | m³ | Zimmer- und Holzbauarbeiten | Wand | Staffel + Zwischendämmung | WA-DL |  |  | 3.75 | 1155HWa0000191819 | NEW | no | yes | 0 | 0.9 |  | 32 | AllplanAttributes - Sicherheitsklasse: -; Sonnenschutztyp: Movable; g-Wert: 0,51
Konterlattung | H2 Ebene +1 | WA-KL | 1155Wa 0000191878 | yes |  | m² | Zimmer- und Holzbauarbeiten | Wand | Konterlattung | WA-KL |  |  | 3.75 | 1155HWa0000191819 | NEW | no | yes | 0 | 0.9 |  | 32 | AllplanAttributes - Sicherheitsklasse: -; Sonnenschutztyp: Movable; g-Wert: 0,51
Traglattung | H2 Ebene +1 | WA-TL | 1155Wa 0000191877 | yes |  | m² | Zimmer- und Holzbauarbeiten | Wand | Traglattung | WA-TL |  |  | 3.75 | 1155HWa0000191819 | NEW | no | yes | 0 | 0.9 |  | 32 | AllplanAttributes - Sicherheitsklasse: -; Sonnenschutztyp: Movable; g-Wert: 0,51
Keramikschindel | H2 Ebene +1 | WA-HS | 1155Wa 0000191876 | yes |  | m² | Zimmer- und Holzbauarbeiten | Wand | Keramikschindel | WA-HS |  |  | 3.75 | 1155HWa0000191819 | NEW | no | yes | 0 | 0.9 |  | 32 | AllplanAttributes - ash D_Detailverweis: FS12; ash D_Plannummer: D1854; Sicherheitsklasse: -; Sonnenschutztyp: Movable; g-Wert: 0,51
 | H2 Ebene +1 | WA-LB | 1155Wa 0000003126 | yes | Codetext | m² | Trockenbauarbeiten | Wand | Außenwand 7-Schalig | WA-LB | 0 | A | 3.75 | 1155HWa0000003028 | NEW | no | yes | 0 | 0.9 | no | 32 | no | Codetext | AllplanAttributes - ash_W_Trockenbau_Qualitäten: 6; Sicherheitsklasse: -; Sonnenschutztyp: Movable; g-Wert: 0,51
 | H2 Ebene +1 | WA-HD | 1155Wa 0000003124 | yes | Codetext | m³ | Zimmer- und Holzbauarbeiten | Wand | Außenwand 7-Schalig | WA-HD | 0 | A | 3.75 | 1155HWa0000003028 | NEW | no | yes | 0 | 0.9 | no | 32 | no | Codetext | AllplanAttributes - ash D_Detailverweis: DT B; ash D_Plannummer: D1851; Sicherheitsklasse: -; Sonnenschutztyp: Movable; g-Wert: 0,51
 | H2 Ebene +1 | WA-DL | 1155Wa 0000003122 | yes | Codetext | m³ | Zimmer- und Holzbauarbeiten | Wand | Außenwand 7-Schalig | WA-DL | 0 | A | 3.75 | 1155HWa0000003028 | NEW | no | yes | 0 | 0.9 | no | 32 | no | Codetext | AllplanAttributes - Sicherheitsklasse: -; Sonnenschutztyp: Movable; g-Wert: 0,51
 | H2 Ebene +1 | WA-LB | 1155Wa 0000003120 | yes | Codetext | m² | Trockenbauarbeiten | Wand | Außenwand 7-Schalig | WA-LB | 0 | A | 3.75 | 1155HWa0000003028 | NEW | no | yes | 0 | 0.9 | no | 32 | no | Codetext | AllplanAttributes - Sicherheitsklasse: -; Sonnenschutztyp: Movable; g-Wert: 0,51
 | H2 Ebene +1 | WA-KL | 1155Wa 0000003118 | yes | Codetext | m² | Zimmer- und Holzbauarbeiten | Wand | Außenwand 7-Schalig | WA-KL | 0 | A | 3.75 | 1155HWa0000003028 | NEW | no | yes | 0 | 0.9 | no | 32 | no | Codetext | AllplanAttributes - Sicherheitsklasse: -; Sonnenschutztyp: Movable; g-Wert: 0,51
 | H2 Ebene +1 | WA-TL | 1155Wa 0000003116 | yes | Codetext | m² | Zimmer- und Holzbauarbeiten | Wand | Außenwand 7-Schalig | WA-TL | 0 | A | 3.75 | 1155HWa0000003028 | NEW | no | yes | 0 | 0.9 | no | 32 | no | Codetext | AllplanAttributes - Sicherheitsklasse: -; Sonnenschutztyp: Movable; g-Wert: 0,51
 | H2 Ebene +1 | WA-HS | 1155Wa 0000003114 | yes | Codetext | m² | Zimmer- und Holzbauarbeiten | Wand | Außenwand 7-Schalig | WA-HS | 0 | A | 3.75 | 1155HWa0000003028 | NEW | no | yes | 0 | 0.9 | no | 32 | no | Codetext | AllplanAttributes - Sicherheitsklasse: -; Sonnenschutztyp: Movable; g-Wert: 0,51
 | H2 Ebene +1 | WA-LB | 1155Wa 0000003877 | yes | Codetext | m² | Trockenbauarbeiten | Wand | Außenwand 7-Schalig | WA-LB | 0 | A | 3.75 | 1155HWa0000003168 | NEW | no | yes | 0 | 0.9 | no | 32 | no | Codetext | AllplanAttributes - Sicherheitsklasse: -; Sonnenschutztyp: Movable; g-Wert: 0,51
 | H2 Ebene +1 | WA-DL | 1155Wa 0000003882 | yes | Codetext | m³ | Zimmer- und Holzbauarbeiten | Wand | Außenwand 7-Schalig | WA-DL | 0 | A | 3.75 | 1155HWa0000003168 | NEW | no | yes | 0 | 0.9 | no | 32 | no | Codetext | AllplanAttributes - Sicherheitsklasse: -; Sonnenschutztyp: Movable; g-Wert: 0,51; ash W_laufende Nr. Statik: 8 (W 10.0)
 | H2 Ebene +1 | WA-DL | 1155Wa 0000003886 | yes | Codetext | m³ | Zimmer- und Holzbauarbeiten | Wand | Außenwand 7-Schalig | WA-DL | 0 | A | 3.75 | 1155HWa0000003168 | NEW | no | yes | 0 | 0.9 | no | 32 | no | Codetext | AllplanAttributes - Sicherheitsklasse: -; Sonnenschutztyp: Movable; g-Wert: 0,51
 | H2 Ebene +1 | WA-DL | 1155Wa 0000003891 | yes | Codetext | m³ | Zimmer- und Holzbauarbeiten | Wand | Außenwand 7-Schalig | WA-DL | 0 | A | 3.75 | 1155HWa0000003168 | NEW | no | yes | 0 | 0.9 | no | 32 | no | Codetext | AllplanAttributes - Sicherheitsklasse: -; Sonnenschutztyp: Movable; g-Wert: 0,51
 | H2 Ebene +1 | WA-LB | 1155Wa 0000003896 | yes | Codetext | m² | Trockenbauarbeiten | Wand | Außenwand 7-Schalig | WA-LB | 0 | A | 3.75 | 1155HWa0000003168 | NEW | no | yes | 0 | 0.9 | no | 32 | no | Codetext | AllplanAttributes - Sicherheitsklasse: -; Sonnenschutztyp: Movable; g-Wert: 0,51
 | H2 Ebene +1 | WA-KL | 1155Wa 0000003901 | yes | Codetext | m² | Zimmer- und Holzbauarbeiten | Wand | Außenwand 7-Schalig | WA-KL | 0 | A | 3.75 | 1155HWa0000003168 | NEW | no | yes | 0 | 0.9 | no | 32 | no | Codetext | AllplanAttributes - Sicherheitsklasse: -; Sonnenschutztyp: Movable; g-Wert: 0,51
 | H2 Ebene +1 | WA-TL | 1155Wa 0000003906 | yes | Codetext | m² | Zimmer- und Holzbauarbeiten | Wand | Außenwand 7-Schalig | WA-TL | 0 | A | 3.75 | 1155HWa0000003168 | NEW | no | yes | 0 | 0.9 | no | 32 | no | Codetext | AllplanAttributes - Sicherheitsklasse: -; Sonnenschutztyp: Movable; g-Wert: 0,51
 | H2 Ebene +1 | WA-HS | 1155Wa 0000210816 | yes | Codetext | m² | Zimmer- und Holzbauarbeiten | Wand | Außenwand 7-Schalig | WA-HS | 0 | A | 3.75 | 1155HWa0000003168 | NEW | no | yes | 0 | 0.9 | no | 32 | no | Codetext | AllplanAttributes - Sicherheitsklasse: -; Sonnenschutztyp: Movable; g-Wert: 0,51
 | H2 Ebene +1 | WA-LB | 1155Wa 0000004015 | yes | Codetext | m² | Trockenbauarbeiten | Wand | Außenwand 7-Schalig | WA-LB | 0 | A | 3.75 | 1155HWa0000003206 | NEW | no | yes | 0 | 0.9 | no | 32 | no | Codetext | AllplanAttributes - Sicherheitsklasse: -; Sonnenschutztyp: Movable; g-Wert: 0,51
 | H2 Ebene +1 | WA-DL | 1155Wa 0000004020 | yes | Codetext | m³ | Zimmer- und Holzbauarbeiten | Wand | Außenwand 7-Schalig | WA-DL | 0 | A | 3.75 | 1155HWa0000003206 | NEW | no | yes | 0 | 0.9 | no | 32 | no | Codetext | AllplanAttributes - ash D_Detailverweis: DT D; ash D_Plannummer: D1851; Sicherheitsklasse: -; Sonnenschutztyp: Movable; g-Wert: 0,51; ash W_laufende Nr. Statik: 2 (W 2.0/ 2.1/ 2.2)
 | H2 Ebene +1 | WA-DL | 1155Wa 0000004024 | yes | Codetext | m³ | Zimmer- und Holzbauarbeiten | Wand | Außenwand 7-Schalig | WA-DL | 0 | A | 3.75 | 1155HWa0000003206 | NEW | no | yes | 0 | 0.9 | no | 32 | no | Codetext | AllplanAttributes - Sicherheitsklasse: -; Sonnenschutztyp: Movable; g-Wert: 0,51
 | H2 Ebene +1 | WA-LB | 1155Wa 0000004029 | yes | Codetext | m² | Trockenbauarbeiten | Wand | Außenwand 7-Schalig | WA-LB | 0 | A | 3.75 | 1155HWa0000003206 | NEW | no | yes | 0 | 0.9 | no | 32 | no | Codetext | AllplanAttributes - Sicherheitsklasse: -; Sonnenschutztyp: Movable; g-Wert: 0,51
 | H2 Ebene +1 | WA-KL | 1155Wa 0000004034 | yes | Codetext | m² | Zimmer- und Holzbauarbeiten | Wand | Außenwand 7-Schalig | WA-KL | 0 | A | 3.75 | 1155HWa0000003206 | NEW | no | yes | 0 | 0.9 | no | 32 | no | Codetext | AllplanAttributes - Sicherheitsklasse: -; Sonnenschutztyp: Movable; g-Wert: 0,51
 | H2 Ebene +1 | WA-TL | 1155Wa 0000004039 | yes | Codetext | m² | Zimmer- und Holzbauarbeiten | Wand | Außenwand 7-Schalig | WA-TL | 0 | A | 3.75 | 1155HWa0000003206 | NEW | no | yes | 0 | 0.9 | no | 32 | no | Codetext | AllplanAttributes - Sicherheitsklasse: -; Sonnenschutztyp: Movable; g-Wert: 0,51
 | H2 Ebene +1 | WA-HS | 1155Wa 0000004044 | yes | Codetext | m² | Zimmer- und Holzbauarbeiten | Wand | Außenwand 7-Schalig | WA-HS | 0 | A | 3.75 | 1155HWa0000003206 | NEW | no | yes | 0 | 0.9 | no | 32 | no | Codetext | AllplanAttributes - Sicherheitsklasse: -; Sonnenschutztyp: Movable; g-Wert: 0,51
 | H2 Ebene +1 | WA-LB | 1155Wa 0000004655 | yes | Codetext | m² | Trockenbauarbeiten | Wand | Außenwand 7-Schalig | WA-LB | 0 | A | 3.75 | 1155HWa0000004247 | NEW | no | yes | 0 | 0.9 | no | 32 | no | Codetext | AllplanAttributes - Sicherheitsklasse: -; Sonnenschutztyp: Movable; g-Wert: 0,51
 | H2 Ebene +1 | WA-DL | 1155Wa 0000004651 | yes | Codetext | m³ | Zimmer- und Holzbauarbeiten | Wand | Außenwand 7-Schalig | WA-DL | 0 | A | 3.75 | 1155HWa0000004247 | NEW | no | yes | 0 | 0.9 | no | 32 | no | Codetext | AllplanAttributes - Sicherheitsklasse: -; Sonnenschutztyp: Movable; g-Wert: 0,51; ash W_laufende Nr. Statik: 2 (W 2.0/ 2.1/ 2.2)
 | H2 Ebene +1 | WA-DL | 1155Wa 0000004647 | yes | Codetext | m³ | Zimmer- und Holzbauarbeiten | Wand | Außenwand 7-Schalig | WA-DL | 0 | A | 3.75 | 1155HWa0000004247 | NEW | no | yes | 0 | 0.9 | no | 32 | no | Codetext | AllplanAttributes - Sicherheitsklasse: -; Sonnenschutztyp: Movable; g-Wert: 0,51
 | H2 Ebene +1 | WA-LB | 1155Wa 0000004643 | yes | Codetext | m² | Trockenbauarbeiten | Wand | Außenwand 7-Schalig | WA-LB | 0 | A | 3.75 | 1155HWa0000004247 | NEW | no | yes | 0 | 0.9 | no | 32 | no | Codetext | AllplanAttributes - Sicherheitsklasse: -; Sonnenschutztyp: Movable; g-Wert: 0,51
 | H2 Ebene +1 | WA-KL | 1155Wa 0000004639 | yes | Codetext | m² | Zimmer- und Holzbauarbeiten | Wand | Außenwand 7-Schalig | WA-KL | 0 | A | 3.75 | 1155HWa0000004247 | NEW | no | yes | 0 | 0.9 | no | 32 | no | Codetext | AllplanAttributes - Sicherheitsklasse: -; Sonnenschutztyp: Movable; g-Wert: 0,51
 | H2 Ebene +1 | WA-TL | 1155Wa 0000004635 | yes | Codetext | m² | Zimmer- und Holzbauarbeiten | Wand | Außenwand 7-Schalig | WA-TL | 0 | A | 3.75 | 1155HWa0000004247 | NEW | no | yes | 0 | 0.9 | no | 32 | no | Codetext | AllplanAttributes - Sicherheitsklasse: -; Sonnenschutztyp: Movable; g-Wert: 0,51
 | H2 Ebene +1 | WA-HS | 1155Wa 0000004631 | yes | Codetext | m² | Zimmer- und Holzbauarbeiten | Wand | Außenwand 7-Schalig | WA-HS | 0 | A | 3.75 | 1155HWa0000004247 | NEW | no | yes | 0 | 0.9 | no | 32 | no | Codetext | AllplanAttributes - Sicherheitsklasse: -; Sonnenschutztyp: Movable; g-Wert: 0,51
2x Gipsfaserplatte | H2 Ebene +1 | WA-LB | 1155Wa 0000004627 | yes |  | m² | Trockenbauarbeiten | Wand | 2x Gipsfaserplatte | WA-LB |  |  | 3.75 | 1155HWa0000004613 | NEW | no | yes | 0 | 0.9 |  | 32 | AllplanAttributes - Sicherheitsklasse: -; Sonnenschutztyp: Movable; g-Wert: 0,51
Holzständer + Zwischendämmung | H2 Ebene +1 | WA-DL | 1155Wa 0000004625 | yes |  | m³ | Zimmer- und Holzbauarbeiten | Wand | Holzständer + Zwischendämmung | WA-DL |  |  | 3.75 | 1155HWa0000004613 | NEW | no | yes | 0 | 0.9 |  | 32 | AllplanAttributes - Sicherheitsklasse: -; Sonnenschutztyp: Movable; g-Wert: 0,51; ash W_laufende Nr. Statik: 2 (W 2.0/ 2.1/ 2.2)
Staffel + Zwischendämmung | H2 Ebene +1 | WA-DL | 1155Wa 0000004623 | yes |  | m³ | Zimmer- und Holzbauarbeiten | Wand | Staffel + Zwischendämmung | WA-DL |  |  | 3.75 | 1155HWa0000004613 | NEW | no | yes | 0 | 0.9 |  | 32 | AllplanAttributes - Sicherheitsklasse: -; Sonnenschutztyp: Movable; g-Wert: 0,51
 | H2 Ebene +1 | WA-LB | 1155Wa 0000004621 | yes | Codetext | m² | Trockenbauarbeiten | Wand | Außenwand 7-Schalig | WA-LB | 0 | A | 3.75 | 1155HWa0000004613 | NEW | no | yes | 0 | 0.9 | no | 32 | no | Codetext | AllplanAttributes - Sicherheitsklasse: -; Sonnenschutztyp: Movable; g-Wert: 0,51
Konterlattung | H2 Ebene +1 | WA-KL | 1155Wa 0000004619 | yes |  | m² | Zimmer- und Holzbauarbeiten | Wand | Konterlattung | WA-KL |  |  | 3.75 | 1155HWa0000004613 | NEW | no | yes | 0 | 0.9 |  | 32 | AllplanAttributes - Sicherheitsklasse: -; Sonnenschutztyp: Movable; g-Wert: 0,51
Traglattung | H2 Ebene +1 | WA-TL | 1155Wa 0000004617 | yes |  | m² | Zimmer- und Holzbauarbeiten | Wand | Traglattung | WA-TL |  |  | 3.75 | 1155HWa0000004613 | NEW | no | yes | 0 | 0.9 |  | 32 | AllplanAttributes - Sicherheitsklasse: -; Sonnenschutztyp: Movable; g-Wert: 0,51
Holzschindel | H2 Ebene +1 | WA-HS | 1155Wa 0000004615 | yes |  | m² | Zimmer- und Holzbauarbeiten | Wand | Holzschindel | WA-HS |  |  | 3.75 | 1155HWa0000004613 | NEW | no | yes | 0 | 0.9 |  | 32 | AllplanAttributes - Sicherheitsklasse: -; Sonnenschutztyp: Movable; g-Wert: 0,51
2x Gipsfaserplatte | H2 Ebene +1 | WA-LB | 1155Wa 0000004583 | yes |  | m² | Trockenbauarbeiten | Wand | 2x Gipsfaserplatte | WA-LB |  |  | 3.75 | 1155HWa0000004569 | NEW | no | yes | 0 | 0.9 |  | 32 | AllplanAttributes - Sicherheitsklasse: -; Sonnenschutztyp: Movable; g-Wert: 0,51
Holzständer + Zwischendämmung | H2 Ebene +1 | WA-DL | 1155Wa 0000004581 | yes |  | m³ | Zimmer- und Holzbauarbeiten | Wand | Holzständer + Zwischendämmung | WA-DL |  |  | 3.75 | 1155HWa0000004569 | NEW | no | yes | 0 | 0.9 |  | 32 | AllplanAttributes - Sicherheitsklasse: -; Sonnenschutztyp: Movable; g-Wert: 0,51; ash W_laufende Nr. Statik: 2 (W 2.0/ 2.1/ 2.2)
Staffel + Zwischendämmung | H2 Ebene +1 | WA-DL | 1155Wa 0000004579 | yes |  | m³ | Zimmer- und Holzbauarbeiten | Wand | Staffel + Zwischendämmung | WA-DL |  |  | 3.75 | 1155HWa0000004569 | NEW | no | yes | 0 | 0.9 |  | 32 | AllplanAttributes - Sicherheitsklasse: -; Sonnenschutztyp: Movable; g-Wert: 0,51
 | H2 Ebene +1 | WA-LB | 1155Wa 0000004577 | yes | Codetext | m² | Trockenbauarbeiten | Wand | Außenwand 7-Schalig | WA-LB | 0 | A | 3.75 | 1155HWa0000004569 | NEW | no | yes | 0 | 0.9 | no | 32 | no | Codetext | AllplanAttributes - Sicherheitsklasse: -; Sonnenschutztyp: Movable; g-Wert: 0,51
Konterlattung | H2 Ebene +1 | WA-KL | 1155Wa 0000004575 | yes |  | m² | Zimmer- und Holzbauarbeiten | Wand | Konterlattung | WA-KL |  |  | 3.75 | 1155HWa0000004569 | NEW | no | yes | 0 | 0.9 |  | 32 | AllplanAttributes - Sicherheitsklasse: -; Sonnenschutztyp: Movable; g-Wert: 0,51
Traglattung | H2 Ebene +1 | WA-TL | 1155Wa 0000004573 | yes |  | m² | Zimmer- und Holzbauarbeiten | Wand | Traglattung | WA-TL |  |  | 3.75 | 1155HWa0000004569 | NEW | no | yes | 0 | 0.9 |  | 32 | AllplanAttributes - Sicherheitsklasse: -; Sonnenschutztyp: Movable; g-Wert: 0,51
Holzschindel | H2 Ebene +1 | WA-HS | 1155Wa 0000004571 | yes |  | m² | Zimmer- und Holzbauarbeiten | Wand | Holzschindel | WA-HS |  |  | 3.75 | 1155HWa0000004569 | NEW | no | yes | 0 | 0.9 |  | 32 | AllplanAttributes - Sicherheitsklasse: -; Sonnenschutztyp: Movable; g-Wert: 0,51
2x Gipsfaserplatte | H2 Ebene +1 | WA-LB | 1155Wa 0000004187 | yes |  | m² | Trockenbauarbeiten | Wand | 2x Gipsfaserplatte | WA-LB |  |  | 3.75 | 1155HWa0000003281 | NEW | no | yes | 0 | 0.9 |  | 32 | AllplanAttributes - Sicherheitsklasse: -; Sonnenschutztyp: Movable; g-Wert: 0,51
Holzständer + Zwischendämmung | H2 Ebene +1 | WA-DL | 1155Wa 0000004189 | yes |  | m³ | Zimmer- und Holzbauarbeiten | Wand | Holzständer + Zwischendämmung | WA-DL |  |  | 3.75 | 1155HWa0000003281 | NEW | no | yes | 0 | 0.9 |  | 32 | AllplanAttributes - Sicherheitsklasse: -; Sonnenschutztyp: Movable; g-Wert: 0,51; ash W_laufende Nr. Statik: 2 (W 2.0/ 2.1/ 2.2)
Staffel + Zwischendämmung | H2 Ebene +1 | WA-DL | 1155Wa 0000004191 | yes |  | m³ | Zimmer- und Holzbauarbeiten | Wand | Staffel + Zwischendämmung | WA-DL |  |  | 3.75 | 1155HWa0000003281 | NEW | no | yes | 0 | 0.9 |  | 32 | AllplanAttributes - Sicherheitsklasse: -; Sonnenschutztyp: Movable; g-Wert: 0,51
 | H2 Ebene +1 | WA-LB | 1155Wa 0000004193 | yes | Codetext | m² | Trockenbauarbeiten | Wand | Außenwand 7-Schalig | WA-LB | 0 | A | 3.75 | 1155HWa0000003281 | NEW | no | yes | 0 | 0.9 | no | 32 | no | Codetext | AllplanAttributes - Sicherheitsklasse: -; Sonnenschutztyp: Movable; g-Wert: 0,51
Konterlattung | H2 Ebene +1 | WA-KL | 1155Wa 0000004195 | yes |  | m² | Zimmer- und Holzbauarbeiten | Wand | Konterlattung | WA-KL |  |  | 3.75 | 1155HWa0000003281 | NEW | no | yes | 0 | 0.9 |  | 32 | AllplanAttributes - Sicherheitsklasse: -; Sonnenschutztyp: Movable; g-Wert: 0,51
Traglattung | H2 Ebene +1 | WA-TL | 1155Wa 0000004197 | yes |  | m² | Zimmer- und Holzbauarbeiten | Wand | Traglattung | WA-TL |  |  | 3.75 | 1155HWa0000003281 | NEW | no | yes | 0 | 0.9 |  | 32 | AllplanAttributes - Sicherheitsklasse: -; Sonnenschutztyp: Movable; g-Wert: 0,51
Holzschindel | H2 Ebene +1 | WA-HS | 1155Wa 0000004199 | yes |  | m² | Zimmer- und Holzbauarbeiten | Wand | Holzschindel | WA-HS |  |  | 3.75 | 1155HWa0000003281 | NEW | no | yes | 0 | 0.9 |  | 32 | AllplanAttributes - Sicherheitsklasse: -; Sonnenschutztyp: Movable; g-Wert: 0,51
2x Gipsfaserplatte | H2 Ebene +1 | WA-LB | 1155Wa 0000004356 | yes |  | m² | Trockenbauarbeiten | Wand | 2x Gipsfaserplatte | WA-LB |  |  | 3.75 | 1155HWa0000004285 | NEW | no | yes | 0 | 0.9 |  | 32 | AllplanAttributes - Sicherheitsklasse: -; Sonnenschutztyp: Movable; g-Wert: 0,51
2x Gipsfaserplatte | H2 Ebene +1 | WA-LB | 1155Wa 0000004360 | yes |  | m² | Trockenbauarbeiten | Wand | 2x Gipsfaserplatte | WA-LB |  |  | 3.75 | 1155HWa0000004285 | NEW | no | yes | 0 | 0.9 |  | 32 | AllplanAttributes - Sicherheitsklasse: -; Sonnenschutztyp: Movable; g-Wert: 0,51
Holzständer + Zwischendämmung | H2 Ebene +1 | WA-DL | 1155Wa 0000004364 | yes |  | m³ | Zimmer- und Holzbauarbeiten | Wand | Holzständer + Zwischendämmung | WA-DL |  |  | 3.75 | 1155HWa0000004285 | NEW | no | yes | 0 | 0.9 |  | 32 | AllplanAttributes - Sicherheitsklasse: -; Sonnenschutztyp: Movable; g-Wert: 0,51
 | H2 Ebene +1 | WA-LB | 1155Wa 0000004368 | yes | Codetext | m² | Trockenbauarbeiten | Wand | Außenwand 7-Schalig | WA-LB | 0 | A | 3.75 | 1155HWa0000004285 | NEW | no | yes | 0 | 0.9 | no | 32 | no | Codetext | AllplanAttributes - Sicherheitsklasse: -; Sonnenschutztyp: Movable; g-Wert: 0,51
 | H2 Ebene +1 | WA-LB | 1155Wa 0000004372 | yes | Codetext | m² | Trockenbauarbeiten | Wand | Außenwand 7-Schalig | WA-LB | 0 | A | 3.75 | 1155HWa0000004285 | NEW | no | yes | 0 | 0.9 | no | 32 | no | Codetext | AllplanAttributes - Sicherheitsklasse: -; Sonnenschutztyp: Movable; g-Wert: 0,51
Staffel + Zwischendämmung | H2 Ebene +1 | WA-DL | 1155Wa 0000004376 | yes |  | m³ | Zimmer- und Holzbauarbeiten | Wand | Staffel + Zwischendämmung | WA-DL |  |  | 3.75 | 1155HWa0000004285 | NEW | no | yes | 0 | 0.9 |  | 32 | AllplanAttributes - Sicherheitsklasse: -; Sonnenschutztyp: Movable; g-Wert: 0,51
Konterlattung | H2 Ebene +1 | WA-KL | 1155Wa 0000004380 | yes |  | m² | Zimmer- und Holzbauarbeiten | Wand | Konterlattung | WA-KL |  |  | 3.75 | 1155HWa0000004285 | NEW | no | yes | 0 | 0.9 |  | 32 | AllplanAttributes - Sicherheitsklasse: -; Sonnenschutztyp: Movable; g-Wert: 0,51
Traglattung | H2 Ebene +1 | WA-TL | 1155Wa 0000162482 | yes |  | m² | Zimmer- und Holzbauarbeiten | Wand | Traglattung | WA-TL |  |  | 3.75 | 1155HWa0000004285 | NEW | no | yes | 0 | 0.9 |  | 32 | AllplanAttributes - Sicherheitsklasse: -; Sonnenschutztyp: Movable; g-Wert: 0,51
Holzschindel | H2 Ebene +1 | WA-HS | 1155Wa 0000162483 | yes |  | m² | Zimmer- und Holzbauarbeiten | Wand | Holzschindel | WA-HS |  |  | 3.75 | 1155HWa0000004285 | NEW | no | yes | 0 | 0.9 |  | 32 | AllplanAttributes - Sicherheitsklasse: -; Sonnenschutztyp: Movable; g-Wert: 0,51
2x Gipsfaserplatte | H2 Ebene +1 | WA-LB | 1155Wa 0000004352 | yes |  | m² | Trockenbauarbeiten | Wand | 2x Gipsfaserplatte | WA-LB |  |  | 3.75 | 1155HWa0000004338 | NEW | no | yes | 0 | 0.9 |  | 32 | AllplanAttributes - Sicherheitsklasse: -; Sonnenschutztyp: Movable; g-Wert: 0,51
Holzständer + Zwischendämmung | H2 Ebene +1 | WA-DL | 1155Wa 0000004350 | yes |  | m³ | Zimmer- und Holzbauarbeiten | Wand | Holzständer + Zwischendämmung | WA-DL |  |  | 3.75 | 1155HWa0000004338 | NEW | no | yes | 0 | 0.9 |  | 32 | AllplanAttributes - Sicherheitsklasse: -; Sonnenschutztyp: Movable; g-Wert: 0,51; ash W_laufende Nr. Statik: 2 (W 2.0/ 2.1/ 2.2)
Staffel + Zwischendämmung | H2 Ebene +1 | WA-DL | 1155Wa 0000004348 | yes |  | m³ | Zimmer- und Holzbauarbeiten | Wand | Staffel + Zwischendämmung | WA-DL |  |  | 3.75 | 1155HWa0000004338 | NEW | no | yes | 0 | 0.9 |  | 32 | AllplanAttributes - Sicherheitsklasse: -; Sonnenschutztyp: Movable; g-Wert: 0,51
 | H2 Ebene +1 | WA-LB | 1155Wa 0000004346 | yes | Codetext | m² | Trockenbauarbeiten | Wand | Außenwand 7-Schalig | WA-LB | 0 | A | 3.75 | 1155HWa0000004338 | NEW | no | yes | 0 | 0.9 | no | 32 | no | Codetext | AllplanAttributes - Sicherheitsklasse: -; Sonnenschutztyp: Movable; g-Wert: 0,51
Konterlattung | H2 Ebene +1 | WA-KL | 1155Wa 0000004344 | yes |  | m² | Zimmer- und Holzbauarbeiten | Wand | Konterlattung | WA-KL |  |  | 3.75 | 1155HWa0000004338 | NEW | no | yes | 0 | 0.9 |  | 32 | AllplanAttributes - Sicherheitsklasse: -; Sonnenschutztyp: Movable; g-Wert: 0,51
Traglattung | H2 Ebene +1 | WA-TL | 1155Wa 0000004342 | yes |  | m² | Zimmer- und Holzbauarbeiten | Wand | Traglattung | WA-TL |  |  | 3.75 | 1155HWa0000004338 | NEW | no | yes | 0 | 0.9 |  | 32 | AllplanAttributes - Sicherheitsklasse: -; Sonnenschutztyp: Movable; g-Wert: 0,51
Holzschindel | H2 Ebene +1 | WA-HS | 1155Wa 0000004340 | yes |  | m² | Zimmer- und Holzbauarbeiten | Wand | Holzschindel | WA-HS |  |  | 3.75 | 1155HWa0000004338 | NEW | no | yes | 0 | 0.9 |  | 32 | AllplanAttributes - Sicherheitsklasse: -; Sonnenschutztyp: Movable; g-Wert: 0,51
 | H2 Ebene +1 | WA-LB | 1155Wa 0000004865 | yes | Codetext | m² | Trockenbauarbeiten | Wand | Außenwand 7-Schalig | WA-LB | 0 | A | 3.75 | 1155HWa0000004158 | NEW | no | yes | 0 | 0.9 | no | 32 | no | Codetext | AllplanAttributes - Sicherheitsklasse: -; Sonnenschutztyp: Movable; g-Wert: 0,51
 | H2 Ebene +1 | WA-DL | 1155Wa 0000004860 | yes | Codetext | m³ | Zimmer- und Holzbauarbeiten | Wand | Außenwand 7-Schalig | WA-DL | 0 | A | 3.75 | 1155HWa0000004158 | NEW | no | yes | 0 | 0.9 | no | 32 | no | Codetext | AllplanAttributes - Sicherheitsklasse: -; Sonnenschutztyp: Movable; g-Wert: 0,51; ash W_laufende Nr. Statik: 2 (W 2.0/ 2.1/ 2.2)
 | H2 Ebene +1 | WA-DL | 1155Wa 0000004855 | yes | Codetext | m³ | Zimmer- und Holzbauarbeiten | Wand | Außenwand 7-Schalig | WA-DL | 0 | A | 3.75 | 1155HWa0000004158 | NEW | no | yes | 0 | 0.9 | no | 32 | no | Codetext | AllplanAttributes - Sicherheitsklasse: -; Sonnenschutztyp: Movable; g-Wert: 0,51
 | H2 Ebene +1 | WA-LB | 1155Wa 0000004850 | yes | Codetext | m² | Trockenbauarbeiten | Wand | Außenwand 7-Schalig | WA-LB | 0 | A | 3.75 | 1155HWa0000004158 | NEW | no | yes | 0 | 0.9 | no | 32 | no | Codetext | AllplanAttributes - Sicherheitsklasse: -; Sonnenschutztyp: Movable; g-Wert: 0,51
 | H2 Ebene +1 | WA-KL | 1155Wa 0000004845 | yes | Codetext | m² | Zimmer- und Holzbauarbeiten | Wand | Außenwand 7-Schalig | WA-KL | 0 | A | 3.75 | 1155HWa0000004158 | NEW | no | yes | 0 | 0.9 | no | 32 | no | Codetext | AllplanAttributes - Sicherheitsklasse: -; Sonnenschutztyp: Movable; g-Wert: 0,51
 | H2 Ebene +1 | WA-TL | 1155Wa 0000004840 | yes | Codetext | m² | Zimmer- und Holzbauarbeiten | Wand | Außenwand 7-Schalig | WA-TL | 0 | A | 3.75 | 1155HWa0000004158 | NEW | no | yes | 0 | 0.9 | no | 32 | no | Codetext | AllplanAttributes - Sicherheitsklasse: -; Sonnenschutztyp: Movable; g-Wert: 0,51
 | H2 Ebene +1 | WA-HS | 1155Wa 0000004835 | yes | Codetext | m² | Zimmer- und Holzbauarbeiten | Wand | Außenwand 7-Schalig | WA-HS | 0 | A | 3.75 | 1155HWa0000004158 | NEW | no | yes | 0 | 0.9 | no | 32 | no | Codetext | AllplanAttributes - Sicherheitsklasse: -; Sonnenschutztyp: Movable; g-Wert: 0,51
 | H2 Ebene +1 | WA-LB | 1155Wa 0000004752 | yes | Codetext | m² | Trockenbauarbeiten | Wand | Außenwand 7-Schalig | WA-LB | 0 | A | 3.75 | 1155HWa0000003230 | NEW | no | yes | 0 | 0.9 | no | 32 | no | Codetext | AllplanAttributes - Sicherheitsklasse: -; Sonnenschutztyp: Movable; g-Wert: 0,51
 | H2 Ebene +1 | WA-DL | 1155Wa 0000004760 | yes | Codetext | m³ | Zimmer- und Holzbauarbeiten | Wand | Außenwand 7-Schalig | WA-DL | 0 | A | 3.75 | 1155HWa0000003230 | NEW | no | yes | 0 | 0.9 | no | 32 | no | Codetext | AllplanAttributes - Sicherheitsklasse: -; Sonnenschutztyp: Movable; g-Wert: 0,51; ash W_laufende Nr. Statik: 8 (W 10.0)
 | H2 Ebene +1 | WA-DL | 1155Wa 0000004801 | yes | Codetext | m³ | Zimmer- und Holzbauarbeiten | Wand | Außenwand 7-Schalig | WA-DL | 0 | A | 3.75 | 1155HWa0000003230 | NEW | no | yes | 0 | 0.9 | no | 32 | no | Codetext | AllplanAttributes - Sicherheitsklasse: -; Sonnenschutztyp: Movable; g-Wert: 0,51
 | H2 Ebene +1 | WA-DL | 1155Wa 0000004792 | yes | Codetext | m³ | Zimmer- und Holzbauarbeiten | Wand | Außenwand 7-Schalig | WA-DL | 0 | A | 3.75 | 1155HWa0000003230 | NEW | no | yes | 0 | 0.9 | no | 32 | no | Codetext | AllplanAttributes - Sicherheitsklasse: -; Sonnenschutztyp: Movable; g-Wert: 0,51
 | H2 Ebene +1 | WA-LB | 1155Wa 0000004784 | yes | Codetext | m² | Trockenbauarbeiten | Wand | Außenwand 7-Schalig | WA-LB | 0 | A | 3.75 | 1155HWa0000003230 | NEW | no | yes | 0 | 0.9 | no | 32 | no | Codetext | AllplanAttributes - Sicherheitsklasse: -; Sonnenschutztyp: Movable; g-Wert: 0,51
 | H2 Ebene +1 | WA-KL | 1155Wa 0000004776 | yes | Codetext | m² | Zimmer- und Holzbauarbeiten | Wand | Außenwand 7-Schalig | WA-KL | 0 | A | 3.75 | 1155HWa0000003230 | NEW | no | yes | 0 | 0.9 | no | 32 | no | Codetext | AllplanAttributes - Sicherheitsklasse: -; Sonnenschutztyp: Movable; g-Wert: 0,51
 | H2 Ebene +1 | WA-TL | 1155Wa 0000004768 | yes | Codetext | m² | Zimmer- und Holzbauarbeiten | Wand | Außenwand 7-Schalig | WA-TL | 0 | A | 3.75 | 1155HWa0000003230 | NEW | no | yes | 0 | 0.9 | no | 32 | no | Codetext | AllplanAttributes - Sicherheitsklasse: -; Sonnenschutztyp: Movable; g-Wert: 0,51
 | H2 Ebene +1 | WA-HS | 1155Wa 0000211980 | yes | Codetext | m² | Zimmer- und Holzbauarbeiten | Wand | Außenwand 7-Schalig | WA-HS | 0 | A | 3.75 | 1155HWa0000003230 | NEW | no | yes | 0 | 0.9 | no | 32 | no | Codetext | AllplanAttributes - Sicherheitsklasse: -; Sonnenschutztyp: Movable; g-Wert: 0,51
 | H2 Ebene +1 | WA-LB | 1155Wa 0000005300 | yes | Codetext | m² | Trockenbauarbeiten | Wand | Außenwand 7-Schalig | WA-LB | 0 | A | 3.75 | 1155HWa0000003236 | NEW | no | yes | 0 | 0.9 | no | 32 | no | Codetext | AllplanAttributes - Sicherheitsklasse: -; Sonnenschutztyp: Movable; g-Wert: 0,51
 | H2 Ebene +1 | WA-DL | 1155Wa 0000005290 | yes | Codetext | m³ | Zimmer- und Holzbauarbeiten | Wand | Außenwand 7-Schalig | WA-DL | 0 | A | 3.75 | 1155HWa0000003236 | NEW | no | yes | 0 | 0.9 | no | 32 | no | Codetext | AllplanAttributes - ash D_Detailverweis: DT D; ash D_Plannummer: D1851; Sicherheitsklasse: -; Sonnenschutztyp: Movable; g-Wert: 0,51; ash W_laufende Nr. Statik: 2 (W 2.0/ 2.1/ 2.2)
 | H2 Ebene +1 | WA-DL | 1155Wa 0000005280 | yes | Codetext | m³ | Zimmer- und Holzbauarbeiten | Wand | Außenwand 7-Schalig | WA-DL | 0 | A | 3.75 | 1155HWa0000003236 | NEW | no | yes | 0 | 0.9 | no | 32 | no | Codetext | AllplanAttributes - Sicherheitsklasse: -; Sonnenschutztyp: Movable; g-Wert: 0,51
 | H2 Ebene +1 | WA-LB | 1155Wa 0000005270 | yes | Codetext | m² | Trockenbauarbeiten | Wand | Außenwand 7-Schalig | WA-LB | 0 | A | 3.75 | 1155HWa0000003236 | NEW | no | yes | 0 | 0.9 | no | 32 | no | Codetext | AllplanAttributes - Sicherheitsklasse: -; Sonnenschutztyp: Movable; g-Wert: 0,51
 | H2 Ebene +1 | WA-KL | 1155Wa 0000005260 | yes | Codetext | m² | Zimmer- und Holzbauarbeiten | Wand | Außenwand 7-Schalig | WA-KL | 0 | A | 3.75 | 1155HWa0000003236 | NEW | no | yes | 0 | 0.9 | no | 32 | no | Codetext | AllplanAttributes - Sicherheitsklasse: -; Sonnenschutztyp: Movable; g-Wert: 0,51
 | H2 Ebene +1 | WA-TL | 1155Wa 0000005250 | yes | Codetext | m² | Zimmer- und Holzbauarbeiten | Wand | Außenwand 7-Schalig | WA-TL | 0 | A | 3.75 | 1155HWa0000003236 | NEW | no | yes | 0 | 0.9 | no | 32 | no | Codetext | AllplanAttributes - Sicherheitsklasse: -; Sonnenschutztyp: Movable; g-Wert: 0,51
 | H2 Ebene +1 | WA-HS | 1155Wa 0000005240 | yes | Codetext | m² | Zimmer- und Holzbauarbeiten | Wand | Außenwand 7-Schalig | WA-HS | 0 | A | 3.75 | 1155HWa0000003236 | NEW | no | yes | 0 | 0.9 | no | 32 | no | Codetext | AllplanAttributes - Sicherheitsklasse: -; Sonnenschutztyp: Movable; g-Wert: 0,51
 | H2 Ebene +1 | WA-LB | 1155Wa 0000005305 | yes | Codetext | m² | Trockenbauarbeiten | Wand | Außenwand 7-Schalig | WA-LB | 0 | A | 3.75 | 1155HWa0000003244 | NEW | no | yes | 0 | 0.9 | no | 32 | no | Codetext | AllplanAttributes - Sicherheitsklasse: -; Sonnenschutztyp: Movable; g-Wert: 0,51
 | H2 Ebene +1 | WA-DL | 1155Wa 0000005310 | yes | Codetext | m³ | Zimmer- und Holzbauarbeiten | Wand | Außenwand 7-Schalig | WA-DL | 0 | A | 3.75 | 1155HWa0000003244 | NEW | no | yes | 0 | 0.9 | no | 32 | no | Codetext | AllplanAttributes - Sicherheitsklasse: -; Sonnenschutztyp: Movable; g-Wert: 0,51; ash W_laufende Nr. Statik: 8 (W 10.0)
 | H2 Ebene +1 | WA-DL | 1155Wa 0000005315 | yes | Codetext | m³ | Zimmer- und Holzbauarbeiten | Wand | Außenwand 7-Schalig | WA-DL | 0 | A | 3.75 | 1155HWa0000003244 | NEW | no | yes | 0 | 0.9 | no | 32 | no | Codetext | AllplanAttributes - Sicherheitsklasse: -; Sonnenschutztyp: Movable; g-Wert: 0,51
 | H2 Ebene +1 | WA-DL | 1155Wa 0000005320 | yes | Codetext | m³ | Zimmer- und Holzbauarbeiten | Wand | Außenwand 7-Schalig | WA-DL | 0 | A | 3.75 | 1155HWa0000003244 | NEW | no | yes | 0 | 0.9 | no | 32 | no | Codetext | AllplanAttributes - Sicherheitsklasse: -; Sonnenschutztyp: Movable; g-Wert: 0,51
 | H2 Ebene +1 | WA-LB | 1155Wa 0000005325 | yes | Codetext | m² | Trockenbauarbeiten | Wand | Außenwand 7-Schalig | WA-LB | 0 | A | 3.75 | 1155HWa0000003244 | NEW | no | yes | 0 | 0.9 | no | 32 | no | Codetext | AllplanAttributes - Sicherheitsklasse: -; Sonnenschutztyp: Movable; g-Wert: 0,51
 | H2 Ebene +1 | WA-KL | 1155Wa 0000005330 | yes | Codetext | m² | Zimmer- und Holzbauarbeiten | Wand | Außenwand 7-Schalig | WA-KL | 0 | A | 3.75 | 1155HWa0000003244 | NEW | no | yes | 0 | 0.9 | no | 32 | no | Codetext | AllplanAttributes - Sicherheitsklasse: -; Sonnenschutztyp: Movable; g-Wert: 0,51
 | H2 Ebene +1 | WA-TL | 1155Wa 0000005335 | yes | Codetext | m² | Zimmer- und Holzbauarbeiten | Wand | Außenwand 7-Schalig | WA-TL | 0 | A | 3.75 | 1155HWa0000003244 | NEW | no | yes | 0 | 0.9 | no | 32 | no | Codetext | AllplanAttributes - Sicherheitsklasse: -; Sonnenschutztyp: Movable; g-Wert: 0,51
 | H2 Ebene +1 | WA-HS | 1155Wa 0000212912 | yes | Codetext | m² | Zimmer- und Holzbauarbeiten | Wand | Außenwand 7-Schalig | WA-HS | 0 | A | 3.75 | 1155HWa0000003244 | NEW | no | yes | 0 | 0.9 | no | 32 | no | Codetext | AllplanAttributes - Sicherheitsklasse: -; Sonnenschutztyp: Movable; g-Wert: 0,51
 | H2 Ebene +1 | WA-LB | 1155Wa 0000005175 | yes | Codetext | m² | Trockenbauarbeiten | Wand | Außenwand 7-Schalig | WA-LB | 0 | A | 3.75 | 1155HWa0000003247 | NEW | no | yes | 0 | 0.9 | no | 32 | no | Codetext | AllplanAttributes - Sicherheitsklasse: -; Sonnenschutztyp: Movable; g-Wert: 0,51
 | H2 Ebene +1 | WA-DL | 1155Wa 0000005180 | yes | Codetext | m³ | Zimmer- und Holzbauarbeiten | Wand | Außenwand 7-Schalig | WA-DL | 0 | A | 3.75 | 1155HWa0000003247 | NEW | no | yes | 0 | 0.9 | no | 32 | no | Codetext | AllplanAttributes - ash D_Detailverweis: DT D; ash D_Plannummer: D1851; Sicherheitsklasse: -; Sonnenschutztyp: Movable; g-Wert: 0,51; ash W_laufende Nr. Statik: 2 (W 2.0/ 2.1/ 2.2)
 | H2 Ebene +1 | WA-DL | 1155Wa 0000005184 | yes | Codetext | m³ | Zimmer- und Holzbauarbeiten | Wand | Außenwand 7-Schalig | WA-DL | 0 | A | 3.75 | 1155HWa0000003247 | NEW | no | yes | 0 | 0.9 | no | 32 | no | Codetext | AllplanAttributes - Sicherheitsklasse: -; Sonnenschutztyp: Movable; g-Wert: 0,51
 | H2 Ebene +1 | WA-LB | 1155Wa 0000005189 | yes | Codetext | m² | Trockenbauarbeiten | Wand | Außenwand 7-Schalig | WA-LB | 0 | A | 3.75 | 1155HWa0000003247 | NEW | no | yes | 0 | 0.9 | no | 32 | no | Codetext | AllplanAttributes - Sicherheitsklasse: -; Sonnenschutztyp: Movable; g-Wert: 0,51
 | H2 Ebene +1 | WA-KL | 1155Wa 0000005194 | yes | Codetext | m² | Zimmer- und Holzbauarbeiten | Wand | Außenwand 7-Schalig | WA-KL | 0 | A | 3.75 | 1155HWa0000003247 | NEW | no | yes | 0 | 0.9 | no | 32 | no | Codetext | AllplanAttributes - Sicherheitsklasse: -; Sonnenschutztyp: Movable; g-Wert: 0,51
 | H2 Ebene +1 | WA-TL | 1155Wa 0000005199 | yes | Codetext | m² | Zimmer- und Holzbauarbeiten | Wand | Außenwand 7-Schalig | WA-TL | 0 | A | 3.75 | 1155HWa0000003247 | NEW | no | yes | 0 | 0.9 | no | 32 | no | Codetext | AllplanAttributes - Sicherheitsklasse: -; Sonnenschutztyp: Movable; g-Wert: 0,51
 | H2 Ebene +1 | WA-HS | 1155Wa 0000005170 | yes | Codetext | m² | Zimmer- und Holzbauarbeiten | Wand | Außenwand 7-Schalig | WA-HS | 0 | A | 3.75 | 1155HWa0000003247 | NEW | no | yes | 0 | 0.9 | no | 32 | no | Codetext | AllplanAttributes - Sicherheitsklasse: -; Sonnenschutztyp: Movable; g-Wert: 0,51
 | H2 Ebene +1 | WA-LB | 1155Wa 2005813680 | yes | Codetext | m² | Trockenbauarbeiten | Wand | Außenwand 7-Schalig | WA-LB | 0 | A | 3.75 | 1155HWa0000000808 | NEW | no | yes | 0 | 0.9 | no | 32 | no | Codetext | AllplanAttributes - Sicherheitsklasse: -; Sonnenschutztyp: Movable; g-Wert: 0,51
 | H2 Ebene +1 | WA-HD | 1155Wa 2005813681 | yes | Codetext | m³ | Zimmer- und Holzbauarbeiten | Wand | Außenwand 7-Schalig | WA-HD | 0 | A | 3.75 | 1155HWa0000000808 | NEW | no | yes | 0 | 0.9 | no | 32 | no | Codetext | AllplanAttributes - Sicherheitsklasse: -; Sonnenschutztyp: Movable; g-Wert: 0,51; ash W_laufende Nr. Statik: 2 (W 2.0/ 2.1/ 2.2)
 | H2 Ebene +1 | WA-DL | 1155Wa 2005813686 | yes | Codetext | m³ | Zimmer- und Holzbauarbeiten | Wand | Außenwand 7-Schalig | WA-DL | 0 | A | 3.75 | 1155HWa0000000808 | NEW | no | yes | 0 | 0.9 | no | 32 | no | Codetext | AllplanAttributes - Sicherheitsklasse: -; Sonnenschutztyp: Movable; g-Wert: 0,51
 | H2 Ebene +1 | WA-LB | 1155Wa 2005813684 | yes | Codetext | m² | Trockenbauarbeiten | Wand | Außenwand 7-Schalig | WA-LB | 0 | A | 3.75 | 1155HWa0000000808 | NEW | no | yes | 0 | 0.9 | no | 32 | no | Codetext | AllplanAttributes - Sicherheitsklasse: -; Sonnenschutztyp: Movable; g-Wert: 0,51
 | H2 Ebene +1 | WA-KL | 1155Wa 2005813685 | yes | Codetext | m² | Zimmer- und Holzbauarbeiten | Wand | Außenwand 7-Schalig | WA-KL | 0 | A | 3.75 | 1155HWa0000000808 | NEW | no | yes | 0 | 0.9 | no | 32 | no | Codetext | AllplanAttributes - Sicherheitsklasse: -; Sonnenschutztyp: Movable; g-Wert: 0,51
 | H2 Ebene +1 | WA-TL | 1155Wa 2005813682 | yes | Codetext | m² | Zimmer- und Holzbauarbeiten | Wand | Außenwand 7-Schalig | WA-TL | 0 | A | 3.75 | 1155HWa0000000808 | NEW | no | yes | 0 | 0.9 | no | 32 | no | Codetext | AllplanAttributes - Sicherheitsklasse: -; Sonnenschutztyp: Movable; g-Wert: 0,51
 | H2 Ebene +1 | WA-HS | 1155Wa 2005813683 | yes | Codetext | m² | Zimmer- und Holzbauarbeiten | Wand | Außenwand 7-Schalig | WA-HS | 0 | A | 3.75 | 1155HWa0000000808 | NEW | no | yes | 0 | 0.9 | no | 32 | no | Codetext | AllplanAttributes - Sicherheitsklasse: -; Sonnenschutztyp: Movable; g-Wert: 0,51
 | H2 Ebene +1 | WA-LB | 1155Wa 2005818912 | yes | Codetext | m² | Trockenbauarbeiten | Wand | Außenwand 7-Schalig | WA-LB | 0 | A | 3.75 | 1155HWa0000000821 | NEW | no | yes | 0 | 0.9 | no | 32 | no | Codetext | AllplanAttributes - Sicherheitsklasse: -; Sonnenschutztyp: Movable; g-Wert: 0,51
 | H2 Ebene +1 | WA-HD | 1155Wa 2005818913 | yes | Codetext | m³ | Zimmer- und Holzbauarbeiten | Wand | Außenwand 7-Schalig | WA-HD | 0 | A | 3.75 | 1155HWa0000000821 | NEW | no | yes | 0 | 0.9 | no | 32 | no | Codetext | AllplanAttributes - ash D_Detailverweis: DT C; ash D_Plannummer: D1851; Sicherheitsklasse: -; Sonnenschutztyp: Movable; g-Wert: 0,51; ash W_laufende Nr. Statik: 2 (W 2.0/ 2.1/ 2.2)
 | H2 Ebene +1 | WA-DL | 1155Wa 2005818919 | yes | Codetext | m³ | Zimmer- und Holzbauarbeiten | Wand | Außenwand 7-Schalig | WA-DL | 0 | A | 3.75 | 1155HWa0000000821 | NEW | no | yes | 0 | 0.9 | no | 32 | no | Codetext | AllplanAttributes - Sicherheitsklasse: -; Sonnenschutztyp: Movable; g-Wert: 0,51
 | H2 Ebene +1 | WA-LB | 1155Wa 2005818917 | yes | Codetext | m² | Trockenbauarbeiten | Wand | Außenwand 7-Schalig | WA-LB | 0 | A | 3.75 | 1155HWa0000000821 | NEW | no | yes | 0 | 0.9 | no | 32 | no | Codetext | AllplanAttributes - Sicherheitsklasse: -; Sonnenschutztyp: Movable; g-Wert: 0,51
 | H2 Ebene +1 | WA-KL | 1155Wa 2005818918 | yes | Codetext | m² | Zimmer- und Holzbauarbeiten | Wand | Außenwand 7-Schalig | WA-KL | 0 | A | 3.75 | 1155HWa0000000821 | NEW | no | yes | 0 | 0.9 | no | 32 | no | Codetext | AllplanAttributes - Sicherheitsklasse: -; Sonnenschutztyp: Movable; g-Wert: 0,51
 | H2 Ebene +1 | WA-TL | 1155Wa 2005818915 | yes | Codetext | m² | Zimmer- und Holzbauarbeiten | Wand | Außenwand 7-Schalig | WA-TL | 0 | A | 3.75 | 1155HWa0000000821 | NEW | no | yes | 0 | 0.9 | no | 32 | no | Codetext | AllplanAttributes - Sicherheitsklasse: -; Sonnenschutztyp: Movable; g-Wert: 0,51
 | H2 Ebene +1 | WA-HS | 1155Wa 2005818916 | yes | Codetext | m² | Zimmer- und Holzbauarbeiten | Wand | Außenwand 7-Schalig | WA-HS | 0 | A | 3.75 | 1155HWa0000000821 | NEW | no | yes | 0 | 0.9 | no | 32 | no | Codetext | AllplanAttributes - Sicherheitsklasse: -; Sonnenschutztyp: Movable; g-Wert: 0,51
 | H2 Ebene +1 | WA-LB | 1155Wa 2005818905 | yes | Codetext | m² | Trockenbauarbeiten | Wand | Außenwand 7-Schalig | WA-LB | 0 | A | 3.75 | 1155HWa0000000817 | NEW | no | yes | 0 | 0.9 | no | 32 | no | Codetext | AllplanAttributes - Sicherheitsklasse: -; Sonnenschutztyp: Movable; g-Wert: 0,51
 | H2 Ebene +1 | WA-HD | 1155Wa 2005818906 | yes | Codetext | m³ | Zimmer- und Holzbauarbeiten | Wand | Außenwand 7-Schalig | WA-HD | 0 | A | 3.75 | 1155HWa0000000817 | NEW | no | yes | 0 | 0.9 | no | 32 | no | Codetext | AllplanAttributes - Sicherheitsklasse: -; Sonnenschutztyp: Movable; g-Wert: 0,51; ash W_laufende Nr. Statik: 2 (W 2.0/ 2.1/ 2.2)
 | H2 Ebene +1 | WA-DL | 1155Wa 2005818911 | yes | Codetext | m³ | Zimmer- und Holzbauarbeiten | Wand | Außenwand 7-Schalig | WA-DL | 0 | A | 3.75 | 1155HWa0000000817 | NEW | no | yes | 0 | 0.9 | no | 32 | no | Codetext | AllplanAttributes - Sicherheitsklasse: -; Sonnenschutztyp: Movable; g-Wert: 0,51
 | H2 Ebene +1 | WA-LB | 1155Wa 2005818909 | yes | Codetext | m² | Trockenbauarbeiten | Wand | Außenwand 7-Schalig | WA-LB | 0 | A | 3.75 | 1155HWa0000000817 | NEW | no | yes | 0 | 0.9 | no | 32 | no | Codetext | AllplanAttributes - Sicherheitsklasse: -; Sonnenschutztyp: Movable; g-Wert: 0,51
 | H2 Ebene +1 | WA-KL | 1155Wa 2005818910 | yes | Codetext | m² | Zimmer- und Holzbauarbeiten | Wand | Außenwand 7-Schalig | WA-KL | 0 | A | 3.75 | 1155HWa0000000817 | NEW | no | yes | 0 | 0.9 | no | 32 | no | Codetext | AllplanAttributes - Sicherheitsklasse: -; Sonnenschutztyp: Movable; g-Wert: 0,51
 | H2 Ebene +1 | WA-TL | 1155Wa 2005818907 | yes | Codetext | m² | Zimmer- und Holzbauarbeiten | Wand | Außenwand 7-Schalig | WA-TL | 0 | A | 3.75 | 1155HWa0000000817 | NEW | no | yes | 0 | 0.9 | no | 32 | no | Codetext | AllplanAttributes - Sicherheitsklasse: -; Sonnenschutztyp: Movable; g-Wert: 0,51
 | H2 Ebene +1 | WA-HS | 1155Wa 2005818908 | yes | Codetext | m² | Zimmer- und Holzbauarbeiten | Wand | Außenwand 7-Schalig | WA-HS | 0 | A | 3.75 | 1155HWa0000000817 | NEW | no | yes | 0 | 0.9 | no | 32 | no | Codetext | AllplanAttributes - Sicherheitsklasse: -; Sonnenschutztyp: Movable; g-Wert: 0,51
 | H2 Ebene +1 | WA-LB | 1155Wa 2005819108 | yes | Codetext | m² | Trockenbauarbeiten | Wand | Außenwand 7-Schalig | WA-LB | 0 | A | 3.75 | 1155HWa0000000811 | NEW | no | yes | 0 | 0.9 | no | 32 | no | Codetext | AllplanAttributes - Sicherheitsklasse: -; Sonnenschutztyp: Movable; g-Wert: 0,51
 | H2 Ebene +1 | WA-HD | 1155Wa 2005819107 | yes | Codetext | m³ | Zimmer- und Holzbauarbeiten | Wand | Außenwand 7-Schalig | WA-HD | 0 | A | 3.75 | 1155HWa0000000811 | NEW | no | yes | 0 | 0.9 | no | 32 | no | Codetext | AllplanAttributes - Sicherheitsklasse: -; Sonnenschutztyp: Movable; g-Wert: 0,51; ash W_laufende Nr. Statik: 2 (W 2.0/ 2.1/ 2.2)
 | H2 Ebene +1 | WA-DL | 1155Wa 2005819102 | yes | Codetext | m³ | Zimmer- und Holzbauarbeiten | Wand | Außenwand 7-Schalig | WA-DL | 0 | A | 3.75 | 1155HWa0000000811 | NEW | no | yes | 0 | 0.9 | no | 32 | no | Codetext | AllplanAttributes - Sicherheitsklasse: -; Sonnenschutztyp: Movable; g-Wert: 0,51
 | H2 Ebene +1 | WA-LB | 1155Wa 2005819104 | yes | Codetext | m² | Trockenbauarbeiten | Wand | Außenwand 7-Schalig | WA-LB | 0 | A | 3.75 | 1155HWa0000000811 | NEW | no | yes | 0 | 0.9 | no | 32 | no | Codetext | AllplanAttributes - Sicherheitsklasse: -; Sonnenschutztyp: Movable; g-Wert: 0,51
 | H2 Ebene +1 | WA-KL | 1155Wa 2005819103 | yes | Codetext | m² | Zimmer- und Holzbauarbeiten | Wand | Außenwand 7-Schalig | WA-KL | 0 | A | 3.75 | 1155HWa0000000811 | NEW | no | yes | 0 | 0.9 | no | 32 | no | Codetext | AllplanAttributes - Sicherheitsklasse: -; Sonnenschutztyp: Movable; g-Wert: 0,51
 | H2 Ebene +1 | WA-TL | 1155Wa 2005819106 | yes | Codetext | m² | Zimmer- und Holzbauarbeiten | Wand | Außenwand 7-Schalig | WA-TL | 0 | A | 3.75 | 1155HWa0000000811 | NEW | no | yes | 0 | 0.9 | no | 32 | no | Codetext | AllplanAttributes - Sicherheitsklasse: -; Sonnenschutztyp: Movable; g-Wert: 0,51
 | H2 Ebene +1 | WA-HS | 1155Wa 2005819105 | yes | Codetext | m² | Zimmer- und Holzbauarbeiten | Wand | Außenwand 7-Schalig | WA-HS | 0 | A | 3.75 | 1155HWa0000000811 | NEW | no | yes | 0 | 0.9 | no | 32 | no | Codetext | AllplanAttributes - Sicherheitsklasse: -; Sonnenschutztyp: Movable; g-Wert: 0,51
 | H2 Ebene +1 | WA-FAS | 1155Wa 2005680083 | yes | Codetext | m² | Vorgehängte Fassaden | Wand | Außenwand mehrschalig | WA-FAS | 0 | A |  | 1106HWa0000000475 | NEW | no | yes | 0 | 0 | no | 0 | no | Codetext
 | H2 Ebene +1 | WA-FAS | 1155Wa 2005680084 | yes | Codetext | m² | Vorgehängte Fassaden | Wand | Außenwand mehrschalig | WA-FAS | 0 | A |  | 1106HWa0000000475 | NEW | no | yes | 0 | 0 | no | 0 | no | Codetext
 | H2 Ebene +1 | WI-SYS | 1155Wa 2005680085 | yes | Codetext | m² | Trockenbauarbeiten | Wand | Außenwand mehrschalig | WI-SYS | 0 | A |  |  | NEW | no | yes | 0 | 0 | no | 0 | no | Codetext
 | H2 Ebene +1 | WI-SYS | 1155Wa 2005680068 | yes | Codetext | m² | Trockenbauarbeiten | Wand | Außenwand mehrschalig | WI-SYS | 0 | A |  |  | NEW | no | yes | 0 | 0 | no | 0 | no | Codetext
 | H2 Ebene +1 | WA-FAS | 1155Wa 2005680069 | yes | Codetext | m² | Vorgehängte Fassaden | Wand | Außenwand mehrschalig | WA-FAS | 0 | A |  | 1106HWa0000000475 | NEW | no | yes | 0 | 0 | no | 0 | no | Codetext
 | H2 Ebene +1 | WA-FAS | 1155Wa 2005680070 | yes | Codetext | m² | Vorgehängte Fassaden | Wand | Außenwand mehrschalig | WA-FAS | 0 | A |  | 1106HWa0000000475 | NEW | no | yes | 0 | 0 | no | 0 | no | Codetext
 | H2 Ebene +1 | WA-FAS | 1155Wa 2005678774 | yes | Codetext | m² | Vorgehängte Fassaden | Wand | Außenwand mehrschalig | WA-FAS | 0 | A |  | 1106HWa0000000475 | NEW | no | yes | 0 | 0 | no | 0 | no | Codetext
 | H2 Ebene +1 | WA-FAS | 1155Wa 2005678775 | yes | Codetext | m² | Vorgehängte Fassaden | Wand | Außenwand mehrschalig | WA-FAS | 0 | A |  | 1106HWa0000000475 | NEW | no | yes | 0 | 0 | no | 0 | no | Codetext
 | H2 Ebene +1 | WI-SYS | 1155Wa 2005678776 | yes | Codetext | m² | Trockenbauarbeiten | Wand | Außenwand mehrschalig | WI-SYS | 0 | A |  |  | NEW | no | yes | 0 | 0 | no | 0 | no | Codetext
 | H2 Ebene +1 | WI-SYS | 1155Wa 2005678777 | yes | Codetext | m² | Trockenbauarbeiten | Wand | Außenwand mehrschalig | WI-SYS | 0 | A |  |  | NEW | no | yes | 0 | 0 | no | 0 | no | Codetext
 | H2 Ebene +1 | WA-FAS | 1155Wa 2005678778 | yes | Codetext | m² | Vorgehängte Fassaden | Wand | Außenwand mehrschalig | WA-FAS | 0 | A |  | 1106HWa0000000475 | NEW | no | yes | 0 | 0 | no | 0 | no | Codetext
 | H2 Ebene +1 | WA-FAS | 1155Wa 2005678779 | yes | Codetext | m² | Vorgehängte Fassaden | Wand | Außenwand mehrschalig | WA-FAS | 0 | A |  | 1106HWa0000000475 | NEW | no | yes | 0 | 0 | no | 0 | no | Codetext
2x Gipsfaserplatte | H2 Ebene +1 | WA-LB | 1155Wa 2005836253 | yes |  | m² | Trockenbauarbeiten | Wand | 2x Gipsfaserplatte | WA-LB |  |  | 3.75 | 1155HWa0000144134 | NEW | no | yes | 0 | 0.9 |  | 32 | AllplanAttributes - Sicherheitsklasse: -; Sonnenschutztyp: Movable; g-Wert: 0,51
Holzständer + Zwischendämmung | H2 Ebene +1 | WA-HD | 1155Wa 2005836254 | yes |  | m³ | Zimmer- und Holzbauarbeiten | Wand | Holzständer + Zwischendämmung | WA-HD |  |  | 3.75 | 1155HWa0000144134 | NEW | no | yes | 0 | 0.9 |  | 32 | AllplanAttributes - Sicherheitsklasse: -; Sonnenschutztyp: Movable; g-Wert: 0,51; ash W_laufende Nr. Statik: 2 (W 2.0/ 2.1/ 2.2)
Staffel + Zwischendämmung | H2 Ebene +1 | WA-DL | 1155Wa 2005836255 | yes |  | m³ | Zimmer- und Holzbauarbeiten | Wand | Staffel + Zwischendämmung | WA-DL |  |  | 3.75 | 1155HWa0000144134 | NEW | no | yes | 0 | 0.9 |  | 32 | AllplanAttributes - Sicherheitsklasse: -; Sonnenschutztyp: Movable; g-Wert: 0,51
 | H2 Ebene +1 | WA-LB | 1155Wa 2005836256 | yes | Codetext | m² | Trockenbauarbeiten | Wand | Außenwand 7-Schalig | WA-LB | 0 | A | 3.75 | 1155HWa0000144134 | NEW | no | yes | 0 | 0.9 | no | 32 | no | Codetext | AllplanAttributes - Sicherheitsklasse: -; Sonnenschutztyp: Movable; g-Wert: 0,51
Konterlattung | H2 Ebene +1 | WA-KL | 1155Wa 2005836257 | yes |  | m² | Zimmer- und Holzbauarbeiten | Wand | Konterlattung | WA-KL |  |  | 3.75 | 1155HWa0000144134 | NEW | no | yes | 0 | 0.9 |  | 32 | AllplanAttributes - Sicherheitsklasse: -; Sonnenschutztyp: Movable; g-Wert: 0,51
Traglattung | H2 Ebene +1 | WA-TL | 1155Wa 2005836258 | yes |  | m² | Zimmer- und Holzbauarbeiten | Wand | Traglattung | WA-TL |  |  | 3.75 | 1155HWa0000144134 | NEW | no | yes | 0 | 0.9 |  | 32 | AllplanAttributes - Sicherheitsklasse: -; Sonnenschutztyp: Movable; g-Wert: 0,51
Holzschindel | H2 Ebene +1 | WA-HS | 1155Wa 2005836259 | yes |  | m² | Zimmer- und Holzbauarbeiten | Wand | Holzschindel | WA-HS |  |  | 3.75 | 1155HWa0000144134 | NEW | no | yes | 0 | 0.9 |  | 32 | AllplanAttributes - Sicherheitsklasse: -; Sonnenschutztyp: Movable; g-Wert: 0,51
 | H2 Ebene +1 | WA-LB | 1155Wa 0000084196 | yes | Codetext | m² | Trockenbauarbeiten | Wand | Außenwand 7-Schalig | WA-LB | 0 | A | 3.75 | 1155HWa0000084195 | NEW | no | yes | 0 | 0.9 | no | 32 | no | Codetext | AllplanAttributes - Sicherheitsklasse: -; Sonnenschutztyp: Movable; g-Wert: 0,51
 | H2 Ebene +1 | WA-HD | 1155Wa 0000084197 | yes | Codetext | m³ | Zimmer- und Holzbauarbeiten | Wand | Außenwand 7-Schalig | WA-HD | 0 | A | 3.75 | 1155HWa0000084195 | NEW | no | yes | 0 | 0.9 | no | 32 | no | Codetext | AllplanAttributes - Sicherheitsklasse: -; Sonnenschutztyp: Movable; g-Wert: 0,51; ash W_laufende Nr. Statik: 2 (W 2.0/ 2.1/ 2.2)
 | H2 Ebene +1 | WA-DL | 1155Wa 0000084198 | yes | Codetext | m³ | Zimmer- und Holzbauarbeiten | Wand | Außenwand 7-Schalig | WA-DL | 0 | A | 3.75 | 1155HWa0000084195 | NEW | no | yes | 0 | 0.9 | no | 32 | no | Codetext | AllplanAttributes - Sicherheitsklasse: -; Sonnenschutztyp: Movable; g-Wert: 0,51
 | H2 Ebene +1 | WA-LB | 1155Wa 0000084199 | yes | Codetext | m² | Trockenbauarbeiten | Wand | Außenwand 7-Schalig | WA-LB | 0 | A | 3.75 | 1155HWa0000084195 | NEW | no | yes | 0 | 0.9 | no | 32 | no | Codetext | AllplanAttributes - Sicherheitsklasse: -; Sonnenschutztyp: Movable; g-Wert: 0,51
 | H2 Ebene +1 | WA-KL | 1155Wa 0000084200 | yes | Codetext | m² | Zimmer- und Holzbauarbeiten | Wand | Außenwand 7-Schalig | WA-KL | 0 | A | 3.75 | 1155HWa0000084195 | NEW | no | yes | 0 | 0.9 | no | 32 | no | Codetext | AllplanAttributes - Sicherheitsklasse: -; Sonnenschutztyp: Movable; g-Wert: 0,51
 | H2 Ebene +1 | WA-TL | 1155Wa 0000084201 | yes | Codetext | m² | Zimmer- und Holzbauarbeiten | Wand | Außenwand 7-Schalig | WA-TL | 0 | A | 3.75 | 1155HWa0000084195 | NEW | no | yes | 0 | 0.9 | no | 32 | no | Codetext | AllplanAttributes - Sicherheitsklasse: -; Sonnenschutztyp: Movable; g-Wert: 0,51
 | H2 Ebene +1 | WA-HS | 1155Wa 0000084202 | yes | Codetext | m² | Zimmer- und Holzbauarbeiten | Wand | Außenwand 7-Schalig | WA-HS | 0 | A | 3.75 | 1155HWa0000084195 | NEW | no | yes | 0 | 0.9 | no | 32 | no | Codetext | AllplanAttributes - Sicherheitsklasse: -; Sonnenschutztyp: Movable; g-Wert: 0,51
 | H2 Ebene +1 | WA-STB | 1155Wa 2005836726 | yes | Codetext | m² | Zimmer- und Holzbauarbeiten | Wand | Außenwand 2-Schalig | WA-STB | 0 | A | 3.75 | 1155HWa0000000032 | NEW |  | yes | 0 | 0 | no | 0 | no | Codetext | AllplanAttributes - Ortscode_Geschoßbezeichnung: E00; Sicherheitsklasse: -
 | H2 Ebene +1 | WA-DL | 1155Wa 2005836728 | yes | Codetext | m³ | Zimmer- und Holzbauarbeiten | Wand | Außenwand 2-Schalig | WA-DL | 0 | A | 3.75 | 1155HWa0000000032 | NEW |  | yes | 0 | 0 | no | 0 | no | Codetext | AllplanAttributes - Ortscode_Geschoßbezeichnung: E00; Sicherheitsklasse: -
 | H2 Ebene +1 | WA-LB | 1155Wa 2005836729 | yes | Codetext | m² | Trockenbauarbeiten | Wand | Außenwand 2-Schalig | WA-LB | 0 | A | 3.75 | 1155HWa0000000032 | NEW |  | yes | 0 | 0 | no | 0 | no | Codetext | AllplanAttributes - Ortscode_Geschoßbezeichnung: E00; Sicherheitsklasse: -
 | H2 Ebene +1 | WA-KL | 1155Wa 2005836730 | yes | Codetext | m² | Zimmer- und Holzbauarbeiten | Wand | Außenwand 2-Schalig | WA-KL | 0 | A | 3.75 | 1155HWa0000000032 | NEW |  | yes | 0 | 0 | no | 0 | no | Codetext | AllplanAttributes - Ortscode_Geschoßbezeichnung: E00; Sicherheitsklasse: -
 | H2 Ebene +1 | WA-TL | 1155Wa 2005836731 | yes | Codetext | m² | Zimmer- und Holzbauarbeiten | Wand | Außenwand 2-Schalig | WA-TL | 0 | A | 3.75 | 1155HWa0000000032 | NEW |  | yes | 0 | 0 | no | 0 | no | Codetext | AllplanAttributes - Ortscode_Geschoßbezeichnung: E00; Sicherheitsklasse: -
Keramikschindel | H2 Ebene +1 | WA-HS | 1155Wa 2005836732 | yes | Codetext | m² | Zimmer- und Holzbauarbeiten | Wand | Keramikschindel | WA-HS | 0 | A | 3.75 | 1155HWa0000000032 | NEW |  | yes | 0 | 0 | no | 0 | no | Codetext | AllplanAttributes - Ortscode_Geschoßbezeichnung: E00; Sicherheitsklasse: -
 | H2 Ebene +1 | WI-LB | 1155Wa 2005837223 | yes | Codetext | m² | Trockenbauarbeiten | Wand | Außenwand 2-Schalig | WI-LB | 0 | A | 3.75 | 1163HWa0812447232 | NEW | no | no | 0 | 0 | no |  | no | Codetext | AllplanAttributes - Ortscode_Geschoßbezeichnung: E00; ash_W_Trockenbau_Qualitäten: 9; Sicherheitsklasse: -; Positionsnummer_Text: U100
 | H2 Ebene +1 | WA-STB | 1155Wa 2005837222 | yes | Codetext | m² | Zimmer- und Holzbauarbeiten | Wand | Außenwand 2-Schalig | WA-STB | 0 | A | 3.75 | 1155HWa0000000032 | NEW | no | yes | 0 | 0 | no | 0 | no | Codetext | AllplanAttributes - Ortscode_Geschoßbezeichnung: E00; Sicherheitsklasse: -
 | H2 Ebene +1 | WA-DL | 1155Wa 2005837221 | yes | Codetext | m³ | Zimmer- und Holzbauarbeiten | Wand | Außenwand 2-Schalig | WA-DL | 0 | A | 3.75 | 1155HWa0000000032 | NEW | no | yes | 0 | 0 | no | 0 | no | Codetext | AllplanAttributes - Ortscode_Geschoßbezeichnung: E00; Sicherheitsklasse: -
 | H2 Ebene +1 | WA-LB | 1155Wa 2005837219 | yes | Codetext | m² | Trockenbauarbeiten | Wand | Außenwand 2-Schalig | WA-LB | 0 | A | 3.75 | 1155HWa0000000032 | NEW | no | yes | 0 | 0 | no | 0 | no | Codetext | AllplanAttributes - Ortscode_Geschoßbezeichnung: E00; Sicherheitsklasse: -
 | H2 Ebene +1 | WA-KL | 1155Wa 2005837218 | yes | Codetext | m² | Zimmer- und Holzbauarbeiten | Wand | Außenwand 2-Schalig | WA-KL | 0 | A | 3.75 | 1155HWa0000000032 | NEW | no | yes | 0 | 0 | no | 0 | no | Codetext | AllplanAttributes - Ortscode_Geschoßbezeichnung: E00; Sicherheitsklasse: -
 | H2 Ebene +1 | WA-TL | 1155Wa 2005837216 | yes | Codetext | m² | Zimmer- und Holzbauarbeiten | Wand | Außenwand 2-Schalig | WA-TL | 0 | A | 3.75 | 1155HWa0000000032 | NEW | no | yes | 0 | 0 | no | 0 | no | Codetext | AllplanAttributes - Ortscode_Geschoßbezeichnung: E00; Sicherheitsklasse: -
Keramikschindel | H2 Ebene +1 | WA-HS | 1155Wa 2005837214 | yes | Codetext | m² | Zimmer- und Holzbauarbeiten | Wand | Keramikschindel | WA-HS | 0 | A | 3.75 | 1155HWa0000000032 | NEW | no | yes | 0 | 0 | no | 0 | no | Codetext | AllplanAttributes - Ortscode_Geschoßbezeichnung: E00; Sicherheitsklasse: -
 | H2 Ebene +1 | WI-LB | 1163Wa 0812443609 |  | Codetext | m² | Trockenbauarbeiten | Wand | Innenwand 1-Schalig | WI-LB | 0 | A | 3.75 | 1163HWa0812430768 | NEW | no | no | REI 30-A1 - D,s2-d0 +A1 | 0 | no | 0 | no | Codetext | AllplanAttributes - Ortscode_Geschoßbezeichnung: E01; W_Deckenanschluss: Gleitender Deckenanschluss Fall 01; ash_W_Trockenbau_Qualitäten: 1b; Positionsnummer_Text: U100
 | H2 Ebene +1 | WI-LB | 1163Wa 0812437641 |  | Codetext | m² | Trockenbauarbeiten | Wand | Innenwand 1-Schalig | WI-LB | 0 | A | 3.75 | 1163HWa0812430724 | NEW | no | no | REI 30-A1 - D,s2-d0 +A1 | 0 | no | 0 | no | Codetext | AllplanAttributes - Ortscode_Geschoßbezeichnung: E01; W_Deckenanschluss: Gleitender Deckenanschluss Fall 01; Positionsnummer_Text: U100
 | H2 Ebene +1 | WI-LB | 1163Wa 0812437388 | yes | Codetext | m² | Trockenbauarbeiten | Wand | Außenwand 1-Schalig | WI-LB | 0 | A | 3.75 | 1163HWa0812425731 | NEW | no | no | REI 60-A1 - D,s2-d0 /A1 | 0 | no | 0 | no | Codetext | AllplanAttributes - Ortscode_Geschoßbezeichnung: E01; W_Deckenanschluss: Gleitender Deckenanschluss Fall 01; ash_W_Trockenbau_Qualitäten: 1b; Positionsnummer_Text: U100
 | H2 Ebene +1 | WI-LB | 1163Wa 0812444147 | yes | Codetext | m² | Trockenbauarbeiten | Wand | Innenwand 1-Schalig | WI-LB | 0 | A | 3.75 | 1163HWa0812444083 | NEW |  | no | REI 60-A1 - D,s2-d0 /A1 | 0 | no | 0 | no | Codetext | AllplanAttributes - Ortscode_Geschoßbezeichnung: E01; W_Deckenanschluss: Gleitender Deckenanschluss Fall 01; ash_W_Trockenbau_Qualitäten: 1b; Positionsnummer_Text: U100
 | H2 Ebene +1 | WI-LB | 1163Wa 0812444161 | yes | Codetext | m² | Trockenbauarbeiten | Wand | Innenwand 1-Schalig | WI-LB | 0 | A | 3.75 | 1163HWa0812444086 | NEW | no | no | REI 60-A1 - D,s2-d0 /A1 | 0 | no | 0 | no | Codetext | AllplanAttributes - Ortscode_Geschoßbezeichnung: E01; W_Deckenanschluss: Gleitender Deckenanschluss Fall 01; ash_W_Trockenbau_Qualitäten: 1b; Positionsnummer_Text: U100
 | H2 Ebene +1 | WI-LB | 1163Wa 0812437392 | yes | Codetext | m² | Trockenbauarbeiten | Wand | Außenwand 1-Schalig | WI-LB | 0 | A | 3.75 | 1163HWa0812425634 | NEW | no | no | REI 60-A1 - D,s2-d0 /A1 | 0 | no | 0 | no | Codetext | AllplanAttributes - Ortscode_Geschoßbezeichnung: E01; W_Deckenanschluss: Gleitender Deckenanschluss Fall 01; ash_W_Trockenbau_Qualitäten: 1b; Positionsnummer_Text: U100
 | H2 Ebene +1 | WI-STB | 1163Wa 0812442055 | yes | Codetext | m² | Zimmer- und Holzbauarbeiten | Wand | Außenwand 1-Schalig | WI-STB | 0 | A | 3.75 | 1163HWa0812428822 | NEW | yes | no | REI 60-A1 - D,s2-d0 /A1 | 0 | no | 0 | no | Codetext | AllplanAttributes - Ortscode_Geschoßbezeichnung: E01; Positionsnummer_Text: U100
 | H2 Ebene +1 | WI-STB | 1163Wa 0812542417 | yes | Codetext | m² | Zimmer- und Holzbauarbeiten | Wand | Außenwand 1-Schalig | WI-STB | 0 | A | 3.75 | 1163HWa0812542403 | NEW | yes | no | REI 60-A1 - D,s2-d0 /A1 | 0 | no | 0 | no | Codetext | AllplanAttributes - Ortscode_Geschoßbezeichnung: E01; Positionsnummer_Text: U100
 | H2 Ebene +1 | WI-LB | 1163Wa 0812549763 | yes | Codetext | m² | Trockenbauarbeiten | Wand | Außenwand 1-Schalig | WI-LB | 0 | A | 3.75 | 1163HWa0812549431 | NEW | no | no | REI 60-A1 - D,s2-d0 /A1 | 0 | no | 0 | no | Codetext | AllplanAttributes - Ortscode_Geschoßbezeichnung: E01; W_Deckenanschluss: Gleitender Deckenanschluss Fall 01; ash_W_Trockenbau_Qualitäten: 1b; Positionsnummer_Text: U100
 | H2 Ebene +1 | WI-LB | 1163Wa 0812437362 |  | Codetext | m² | Trockenbauarbeiten | Wand | Innenwand 1-Schalig | WI-LB | 0 | A | 3.75 | 1163HWa0812430757 | NEW |  | no | REI 60-A1 - D,s2-d0 +A1 | 0 | no | 0 | no | Codetext | AllplanAttributes - Ortscode_Geschoßbezeichnung: E01; W_Deckenanschluss: Gleitender Deckenanschluss Fall 01; ash_W_Trockenbau_Qualitäten: 1b; Positionsnummer_Text: U100
 | H2 Ebene +1 | WI-LB | 1163Wa 0812437390 | yes | Codetext | m² | Trockenbauarbeiten | Wand | Innenwand 1-Schalig | WI-LB | 0 | A | 3.75 | 1163HWa0812425633 | NEW | no | no | REI 60-A1 - D,s2-d0 /A1 | 0 | no | 0 | no | Codetext | AllplanAttributes - Ortscode_Geschoßbezeichnung: E01; W_Deckenanschluss: Gleitender Deckenanschluss Fall 01; ash_W_Trockenbau_Qualitäten: 1b; Positionsnummer_Text: U100
 | H2 Ebene +1 | WI-HW 60 | 1163Wa 0812442585 | yes | Codetext | m² | Zimmer- und Holzbauarbeiten | Wand | Innenwand 1-Schalig | WI-HW 60 | 0 | A | 3.75 | 1163HWa0812440855 | NEW | yes | no | REI 60-A1 - D,s2-d0 +A1 | 0 | no | 0 | no | Codetext | AllplanAttributes - Ortscode_Geschoßbezeichnung: E01; ash W_laufende Nr. Statik: 3 (W 3.0); Positionsnummer_Text: U100
 | H2 Ebene +1 | WI-HW 60 | 1163Wa 0812443622 | yes | Codetext | m² | Zimmer- und Holzbauarbeiten | Wand | Innenwand 1-Schalig | WI-HW 60 | 0 | A | 3.75 | 1163HWa0812440862 | NEW | yes | no | REI 60-A1 - D,s2-d0 +A1 | 0 | no | 0 | no | Codetext | AllplanAttributes - Ortscode_Geschoßbezeichnung: E01; ash W_laufende Nr. Statik: 3 (W 3.0); Positionsnummer_Text: U100
 | H2 Ebene +1 | WI-HW 60 | 1163Wa 0812443694 | yes | Codetext | m² | Zimmer- und Holzbauarbeiten | Wand | Innenwand 1-Schalig | WI-HW 60 | 0 | A | 3.75 | 1163HWa0812425834 | NEW | yes | no | REI 30-A1 - D,s2-d0 +A1 | 0 | no | 0 | no | Codetext | AllplanAttributes - Ortscode_Geschoßbezeichnung: E01; ash W_laufende Nr. Statik: 3 (W 3.0); Positionsnummer_Text: U100
 | H2 Ebene +1 | WI-HW 60 | 1163Wa 0812437257 | yes | Codetext | m² | Zimmer- und Holzbauarbeiten | Wand | Innenwand 1-Schalig | WI-HW 60 | 0 | A | 3.75 | 1163HWa0812434402 | NEW | yes | no | REI 60-A1 - D,s2-d0 /A1 | 0 | no | 0 | no | Codetext | AllplanAttributes - Ortscode_Geschoßbezeichnung: E01; ash W_laufende Nr. Statik: 3 (W 3.0); Positionsnummer_Text: U100
 | H2 Ebene +1 | WI-HW 60 | 1163Wa 0812437646 | yes | Codetext | m² | Zimmer- und Holzbauarbeiten | Wand | Innenwand 1-Schalig | WI-HW 60 | 0 | A | 3.75 | 1163HWa0812430721 | NEW | yes | no | 0 | 0 | no | 0 | no | Codetext | AllplanAttributes - Ortscode_Geschoßbezeichnung: E01; ash W_laufende Nr. Statik: 3 (W 3.0); Positionsnummer_Text: U100
 | H2 Ebene +1 | WI-HW 60 | 1163Wa 0812655407 | yes | Codetext | m² | Zimmer- und Holzbauarbeiten | Wand | Innenwand 1-Schalig | WI-HW 60 | 0 | A | 3.75 | 1163HWa0812655397 | NEW | yes | no | REI 30-A1 - D,s2-d0 +A1 | 0 | no | 0 | no | Codetext | AllplanAttributes - Ortscode_Geschoßbezeichnung: E01; ash W_laufende Nr. Statik: 3 (W 3.0); Positionsnummer_Text: U100
 | H2 Ebene +1 | WI-HW 60 | 1163Wa 0812437643 | yes | Codetext | m² | Zimmer- und Holzbauarbeiten | Wand | Innenwand 1-Schalig | WI-HW 60 | 0 | A | 3.75 | 1163HWa0812430720 | NEW | yes | no | REI 30-A1 - D,s2-d0 +A1 | 0 | no | 0 | no | Codetext | AllplanAttributes - Ortscode_Geschoßbezeichnung: E01; ash W_laufende Nr. Statik: 3 (W 3.0); Positionsnummer_Text: U100
 | H2 Ebene +1 | WI-HW 60 | 1163Wa 0812437364 | yes | Codetext | m² | Zimmer- und Holzbauarbeiten | Wand | Innenwand 1-Schalig | WI-HW 60 | 0 | A | 3.75 | 1163HWa0812430730 | NEW | yes | no | REI 60-A1 - D,s2-d0 +A1 | 0 | no | 0 | no | Codetext | AllplanAttributes - Ortscode_Geschoßbezeichnung: E01; ash W_laufende Nr. Statik: 3 (W 3.0); Positionsnummer_Text: U100
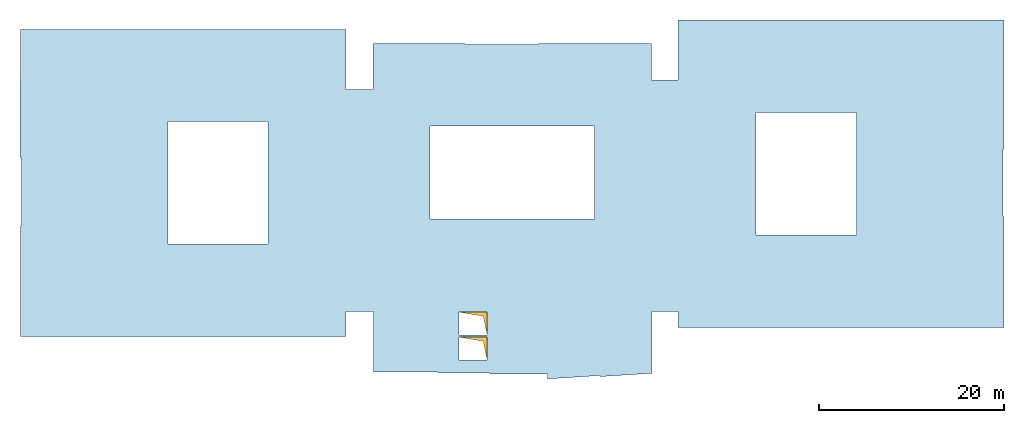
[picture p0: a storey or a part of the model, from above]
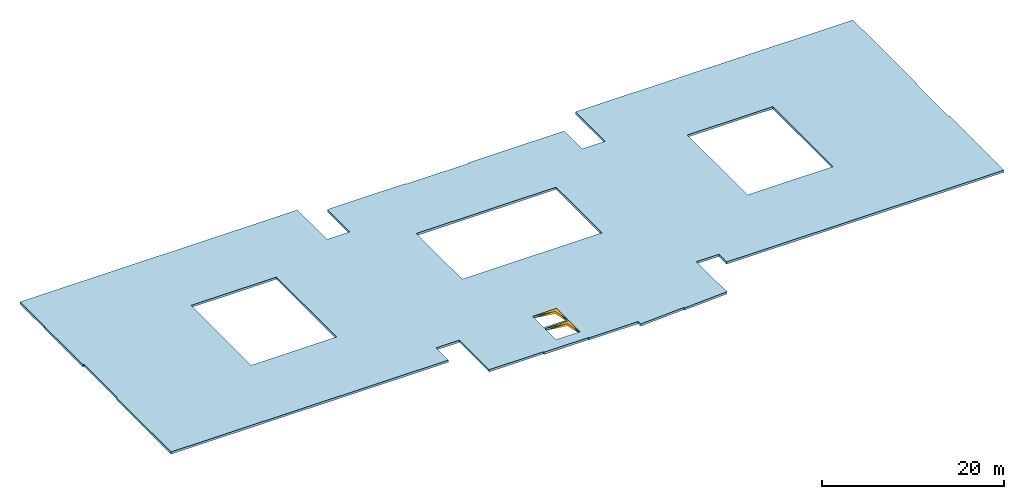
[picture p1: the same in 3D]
Properties of the parts of a building model (IFC4), part 63 of 80

# IfcWall (6826)
Name | In | Material | Allright_Bauteil_ID | 2D Interaktion | Codetext | Abrechnungsart | Gewerk | Objektname | Bezeichnung | AllplanAttributes, Material | Typ = SurfaceSpreadOfFlame | Brandschutzklasse | OKFF | P_ID | Status | LoadBearing | IsExternal | FireRating | ThermalTransmittance (W/K/m2) | Combustible | AcousticRating | Compartmentation | Reference
 | H2 Ebene +1 | WI-HW 60 | 1163Wa 0812437360 | yes | Codetext | m² | Zimmer- und Holzbauarbeiten | Wand | Innenwand 1-Schalig | WI-HW 60 | 0 | A | 3.75 | 1163HWa0812430755 | NEW | yes | no | REI 60-A1 - D,s2-d0 +A1 | 0 | no | 0 | no | Codetext | AllplanAttributes - Ortscode_Geschoßbezeichnung: E01; ash W_laufende Nr. Statik: 3 (W 3.0); Positionsnummer_Text: U100
 | H2 Ebene +1 | WI-LB | 1163Wa 0812444053 |  | Codetext | m² | Trockenbauarbeiten | Wand | Innenwand 1-Schalig | WI-LB | 0 | A | 3.75 | 1163HWa0812425631 | NEW | no | no | REI 60-A1 - D,s2-d0 /A1 | 0 | no | 0 | no | Codetext | AllplanAttributes - Ortscode_Geschoßbezeichnung: E01; W_Deckenanschluss: Gleitender Deckenanschluss Fall 01; ash_W_Trockenbau_Qualitäten: 1b; Positionsnummer_Text: U100
 | H2 Ebene +1 | WI-LB | 1163Wa 0812446036 |  | Codetext | m² | Trockenbauarbeiten | Wand |  |  | 0 | A | 3.75 | 1163HWa0812445209 | NEW | no | no | 0 | 0 | no | 0 | no | Codetext | AllplanAttributes - Ortscode_Geschoßbezeichnung: E01; W_Deckenanschluss: Gleitender Deckenanschluss Fall 03; ash_W_Trockenbau_Qualitäten: 10a; Positionsnummer_Text: U100
 | H2 Ebene +1 | WI-LB | 1163Wa 0812446187 |  | Codetext | m² | Trockenbauarbeiten | Wand |  |  | 0 | A | 3.75 | 1163HWa0812445211 | NEW | no | no | 0 | 0 | no | 0 | no | Codetext | AllplanAttributes - Ortscode_Geschoßbezeichnung: E01; W_Deckenanschluss: Gleitender Deckenanschluss Fall 03; ash_W_Trockenbau_Qualitäten: 10a; Positionsnummer_Text: U100
 | H2 Ebene +1 | WI-LB | 1163Wa 0812446175 |  | Codetext | m² | Trockenbauarbeiten | Wand |  |  | 0 | A | 3.75 | 1163HWa0812445222 | NEW | no | no | 0 | 0 | no | 0 | no | Codetext | AllplanAttributes - Ortscode_Geschoßbezeichnung: E01; W_Deckenanschluss: Gleitender Deckenanschluss Fall 03; ash_W_Trockenbau_Qualitäten: 10a; Positionsnummer_Text: U100
 | H2 Ebene +1 | WI-LB | 1163Wa 0812446039 |  | Codetext | m² | Trockenbauarbeiten | Wand |  |  | 0 | A | 3.75 | 1163HWa0812445223 | NEW | no | no | 0 | 0 | no | 0 | no | Codetext | AllplanAttributes - Ortscode_Geschoßbezeichnung: E01; W_Deckenanschluss: Gleitender Deckenanschluss Fall 03; ash_W_Trockenbau_Qualitäten: 10a; Positionsnummer_Text: U100
 | H2 Ebene +1 | WI-LB | 1163Wa 0812446183 |  | Codetext | m² | Trockenbauarbeiten | Wand |  |  | 0 | A | 3.75 | 1163HWa0812445224 | NEW | no | no | 0 | 0 | no | 0 | no | Codetext | AllplanAttributes - Ortscode_Geschoßbezeichnung: E01; W_Deckenanschluss: Gleitender Deckenanschluss Fall 03; ash_W_Trockenbau_Qualitäten: 10a; Positionsnummer_Text: U100
 | H2 Ebene +1 | WI-LB | 1163Wa 0812446042 |  | Codetext | m² | Trockenbauarbeiten | Wand |  |  | 0 | A | 3.75 | 1163HWa0812445236 | NEW | no | no | 0 | 0 | no | 0 | no | Codetext | AllplanAttributes - Ortscode_Geschoßbezeichnung: E01; W_Deckenanschluss: Gleitender Deckenanschluss Fall 03; ash_W_Trockenbau_Qualitäten: 10a; Positionsnummer_Text: U100
 | H2 Ebene +1 | WI-LB | 1163Wa 0812446179 |  | Codetext | m² | Trockenbauarbeiten | Wand |  |  | 0 | A | 3.75 | 1163HWa0812445237 | NEW | no | no | 0 | 0 | no | 0 | no | Codetext | AllplanAttributes - Ortscode_Geschoßbezeichnung: E01; W_Deckenanschluss: Gleitender Deckenanschluss Fall 03; ash_W_Trockenbau_Qualitäten: 10a; Positionsnummer_Text: U100
 | H2 Ebene +1 | WI-LB | 1163Wa 0812446167 |  | Codetext | m² | Trockenbauarbeiten | Wand |  |  | 0 | A | 3.75 | 1163HWa0812445238 | NEW | no | no | 0 | 0 | no | 0 | no | Codetext | AllplanAttributes - Ortscode_Geschoßbezeichnung: E01; W_Deckenanschluss: Gleitender Deckenanschluss Fall 03; ash_W_Trockenbau_Qualitäten: 10a; Positionsnummer_Text: U100
 | H2 Ebene +1 | WI-LB | 1163Wa 0812446738 |  | Codetext | m² | Trockenbauarbeiten | Wand |  |  | 0 | A | 3.75 | 1163HWa0812446710 | NEW | no | no | 0 | 0 | no | 0 | no | Codetext | AllplanAttributes - Ortscode_Geschoßbezeichnung: E01; W_Deckenanschluss: Gleitender Deckenanschluss Fall 03; ash_W_Trockenbau_Qualitäten: 10a; Positionsnummer_Text: U100
 | H2 Ebene +1 | WI-LB | 1163Wa 0812812970 | yes | Codetext | m² | Trockenbauarbeiten | Wand | Innenwand 1-Schalig | WI-LB | 0 | A | 3.75 | 1163HWa0812812969 | NEW | no | no | REI 60-A1 - D,s2-d0 /A1 | 0 | no | 0 | no | Codetext | AllplanAttributes - Ortscode_Geschoßbezeichnung: E01; ash_W_Trockenbau_Qualitäten: 9; Positionsnummer_Text: U100
 | H2 Ebene +1 | WI-STB | 1163Wa 0812437396 | yes | Codetext | m² | Zimmer- und Holzbauarbeiten | Wand | Außenwand 1-Schalig | WI-STB | 0 | A | 3.75 | 1163HWa0812434260 | NEW | yes | no | REI 60-A1 - D,s2-d0 /A1 | 0 | no | 0 | no | Codetext | AllplanAttributes - Ortscode_Geschoßbezeichnung: E01; Positionsnummer_Text: U100
 | H2 Ebene +1 | WI-LB | 1163Wa 0812543040 | yes | Codetext | m² | Trockenbauarbeiten | Wand | Innenwand 1-Schalig | WI-LB | 0 | A | 3.75 | 1163HWa0812543038 | NEW | no | no | REI 60-A1 - D,s2-d0 /A1 | 0 | no | 0 | no | Codetext | AllplanAttributes - Ortscode_Geschoßbezeichnung: E01; W_Deckenanschluss: Gleitender Deckenanschluss Fall 01; ash_W_Trockenbau_Qualitäten: 13; Positionsnummer_Text: U100
 | H2 Ebene +1 | WI-LB | 1163Wa 0812440263 |  | Codetext | m² | Trockenbauarbeiten | Wand |  |  | 0 | A | 3.75 | 1163HWa0812440129 | NEW | no | no | 0 | 0 | no | 0 | no | Codetext | AllplanAttributes - Ortscode_Geschoßbezeichnung: E01; W_Deckenanschluss: Gleitender Deckenanschluss Fall 03; ash_W_Trockenbau_Qualitäten: 10a; Positionsnummer_Text: U100
 | H2 Ebene +1 | WI-LB | 1163Wa 0812440257 |  | Codetext | m² | Trockenbauarbeiten | Wand |  |  | 0 | A | 3.75 | 1163HWa0812440130 | NEW | no | no | 0 | 0 | no | 0 | no | Codetext | AllplanAttributes - Ortscode_Geschoßbezeichnung: E01; W_Deckenanschluss: Gleitender Deckenanschluss Fall 03; ash_W_Trockenbau_Qualitäten: 10a; Positionsnummer_Text: U100
 | H2 Ebene +1 | WI-LB | 1163Wa 0812437366 |  | Codetext | m² | Trockenbauarbeiten | Wand | Innenwand 1-Schalig | WI-LB | 0 | A | 3.75 | 1163HWa0812430731 | NEW | no | no | REI 60-A1 - D,s2-d0 +A1 | 0 | no | 0 | no | Codetext | AllplanAttributes - Ortscode_Geschoßbezeichnung: E01; W_Deckenanschluss: Gleitender Deckenanschluss Fall 01; ash_W_Trockenbau_Qualitäten: 1b; Positionsnummer_Text: U100
 | H2 Ebene +1 | WI-LB | 1163Wa 0812437721 |  | Codetext | m² | Trockenbauarbeiten | Wand |  |  | 0 | A | 3.75 | 1163HWa0812425520 | NEW | no | no | 0 | 0 | no | 0 | no | Codetext | AllplanAttributes - Ortscode_Geschoßbezeichnung: E01; W_Deckenanschluss: Gleitender Deckenanschluss Fall 03; ash_W_Trockenbau_Qualitäten: 10a; Positionsnummer_Text: U100
 | H2 Ebene +1 | WI-LB | 1163Wa 0812438242 |  | Codetext | m² | Trockenbauarbeiten | Wand |  |  | 0 | A | 3.75 | 1163HWa0812425521 | NEW | no | no | 0 | 0 | no | 0 | no | Codetext | AllplanAttributes - Ortscode_Geschoßbezeichnung: E01; W_Deckenanschluss: Gleitender Deckenanschluss Fall 03; ash_W_Trockenbau_Qualitäten: 10a; Positionsnummer_Text: U100
 | H2 Ebene +1 | WI-LB | 1163Wa 0812438246 |  | Codetext | m² | Trockenbauarbeiten | Wand |  |  | 0 | A | 3.75 | 1163HWa0812425522 | NEW | no | no | 0 | 0 | no | 0 | no | Codetext | AllplanAttributes - Ortscode_Geschoßbezeichnung: E01; W_Deckenanschluss: Gleitender Deckenanschluss Fall 03; ash_W_Trockenbau_Qualitäten: 10a; Positionsnummer_Text: U100
 | H2 Ebene +1 | WI-LB | 1163Wa 0812438254 |  | Codetext | m² | Trockenbauarbeiten | Wand |  |  | 0 | A | 3.75 | 1163HWa0812425535 | NEW | no | no | 0 | 0 | no | 0 | no | Codetext | AllplanAttributes - Ortscode_Geschoßbezeichnung: E01; W_Deckenanschluss: Gleitender Deckenanschluss Fall 03; ash_W_Trockenbau_Qualitäten: 10a; Positionsnummer_Text: U100
 | H2 Ebene +1 | WI-LB | 1163Wa 0812437715 |  | Codetext | m² | Trockenbauarbeiten | Wand |  |  | 0 | A | 3.75 | 1163HWa0812425540 | NEW | no | no | 0 | 0 | no | 0 | no | Codetext | AllplanAttributes - Ortscode_Geschoßbezeichnung: E01; W_Deckenanschluss: Gleitender Deckenanschluss Fall 03; ash_W_Trockenbau_Qualitäten: 10a; Positionsnummer_Text: U100
 | H2 Ebene +1 | WI-LB | 1163Wa 0812438258 |  | Codetext | m² | Trockenbauarbeiten | Wand |  |  | 0 | A | 3.75 | 1163HWa0812425544 | NEW | no | no | 0 | 0 | no | 0 | no | Codetext | AllplanAttributes - Ortscode_Geschoßbezeichnung: E01; W_Deckenanschluss: Gleitender Deckenanschluss Fall 03; ash_W_Trockenbau_Qualitäten: 10a; Positionsnummer_Text: U100
 | H2 Ebene +1 | WI-LB | 1163Wa 0812438238 |  | Codetext | m² | Trockenbauarbeiten | Wand |  |  | 0 | A | 3.75 | 1163HWa0812425553 | NEW | no | no | 0 | 0 | no | 0 | no | Codetext | AllplanAttributes - Ortscode_Geschoßbezeichnung: E01; W_Deckenanschluss: Gleitender Deckenanschluss Fall 03; ash_W_Trockenbau_Qualitäten: 10a; Positionsnummer_Text: U100
 | H2 Ebene +1 | WI-LB | 1163Wa 0812437717 |  | Codetext | m² | Trockenbauarbeiten | Wand |  |  | 0 | A | 3.75 | 1163HWa0812425554 | NEW | no | no | 0 | 0 | no | 0 | no | Codetext | AllplanAttributes - Ortscode_Geschoßbezeichnung: E01; W_Deckenanschluss: Gleitender Deckenanschluss Fall 03; ash_W_Trockenbau_Qualitäten: 10a; Positionsnummer_Text: U100
 | H2 Ebene +1 | WI-LB | 1163Wa 0812438250 |  | Codetext | m² | Trockenbauarbeiten | Wand |  |  | 0 | A | 3.75 | 1163HWa0812425584 | NEW | no | no | 0 | 0 | no | 0 | no | Codetext | AllplanAttributes - Ortscode_Geschoßbezeichnung: E01; W_Deckenanschluss: Gleitender Deckenanschluss Fall 03; ash_W_Trockenbau_Qualitäten: 10a; Positionsnummer_Text: U100
 | H2 Ebene +1 | WI-IW | 1163Wa 0812464612 | yes | Codetext | m² | Trockenbauarbeiten | Wand | Installationswand | WI-IW | 0 | A | 3.75 | 1163HWa0812464611 | NEW |  | no | 0 | 0 | no | 0 | no | Codetext | AllplanAttributes - Ortscode_Geschoßbezeichnung: E01; W_Deckenanschluss: Gleitender Deckenanschluss Fall 01; ash_W_Trockenbau_Qualitäten: 18; Positionsnummer_Text: U100
 | H2 Ebene +1 | WI-LB | 1163Wa 0812468458 |  | Codetext | m² | Trockenbauarbeiten | Wand |  |  | 0 | A | 3.75 | 1163HWa0812468444 | NEW | no | no | 0 | 0 | no | 0 | no | Codetext | AllplanAttributes - Ortscode_Geschoßbezeichnung: E01; W_Deckenanschluss: Gleitender Deckenanschluss Fall 03; ash_W_Trockenbau_Qualitäten: 10a; Positionsnummer_Text: U100
 | H2 Ebene +1 | WI-LB | 1163Wa 0812442711 |  | Codetext | m² | Trockenbauarbeiten | Wand | Innenwand 1-Schalig | WI-LB | 0 | A | 3.75 | 1163HWa0812430771 | NEW | no | no | REI 60-A1 - D,s2-d0 +A1 | 0 | no | 0 | no | Codetext | AllplanAttributes - Ortscode_Geschoßbezeichnung: E01; W_Deckenanschluss: Gleitender Deckenanschluss Fall 01; ash_W_Trockenbau_Qualitäten: 1b; Positionsnummer_Text: U100
 | H2 Ebene +1 | WI-LB | 1163Wa 0812809798 | yes | Codetext | m² | Trockenbauarbeiten | Wand | Innenwand 1-Schalig | WI-LB | 0 | A | 3.75 | 1163HWa0812809797 | NEW | no | no | REI 60-A1 - D,s2-d0 /A1 | 0 | no |  | no | Codetext | AllplanAttributes - Ortscode_Geschoßbezeichnung: E01; ash_W_Trockenbau_Qualitäten: 9; Positionsnummer_Text: U100
 | H2 Ebene +1 | WI-LB | 1163Wa 0812839961 | yes | Codetext | m² | Trockenbauarbeiten | Wand | Innenwand 1-Schalig | WI-LB | 0 | A | 3.75 | 1163HWa0812839960 | NEW | no | no | REI 60-A1 - D,s2-d0 /A1 | 0 | no |  | no | Codetext | AllplanAttributes - Ortscode_Geschoßbezeichnung: E01; ash_W_Trockenbau_Qualitäten: 9; Positionsnummer_Text: U100
 | H2 Ebene +1 | WI-LB | 1163Wa 0812839979 | yes | Codetext | m² | Trockenbauarbeiten | Wand | Innenwand 1-Schalig | WI-LB | 0 | A | 3.75 | 1163HWa0812839978 | NEW | no | no | REI 60-A1 - D,s2-d0 /A1 | 0 | no |  | no | Codetext | AllplanAttributes - Ortscode_Geschoßbezeichnung: E01; ash_W_Trockenbau_Qualitäten: 9; Positionsnummer_Text: U100
 | H2 Ebene +1 | WI-LB | 1163Wa 0812840038 | yes | Codetext | m² | Trockenbauarbeiten | Wand | Innenwand 1-Schalig | WI-LB | 0 | A | 3.75 | 1163HWa0812840037 | NEW | no | no | REI 60-A1 - D,s2-d0 /A1 | 0 | no |  | no | Codetext | AllplanAttributes - Ortscode_Geschoßbezeichnung: E01; ash_W_Trockenbau_Qualitäten: 9; Positionsnummer_Text: U100
 | H2 Ebene +1 | WI-LB | 1163Wa 0812810801 | yes | Codetext | m² | Trockenbauarbeiten | Wand | Innenwand 1-Schalig | WI-LB | 0 | A | 3.75 | 1163HWa0812810800 | NEW | no | no | REI 60-A1 - D,s2-d0 /A1 | 0 | no | 0 | no | Codetext | AllplanAttributes - Ortscode_Geschoßbezeichnung: E01; ash_W_Trockenbau_Qualitäten: 9; Positionsnummer_Text: U100
 | H2 Ebene +1 | WI-LB | 1163Wa 0812840870 | yes | Codetext | m² | Trockenbauarbeiten | Wand | Innenwand 1-Schalig | WI-LB | 0 | A | 3.75 | 1163HWa0812840869 | NEW | no | no | REI 60-A1 - D,s2-d0 /A1 | 0 | no | 0 | no | Codetext | AllplanAttributes - Ortscode_Geschoßbezeichnung: E01; ash_W_Trockenbau_Qualitäten: 9; Positionsnummer_Text: U100
 | H2 Ebene +1 | WI-LB | 1163Wa 0812841138 | yes | Codetext | m² | Trockenbauarbeiten | Wand | Innenwand 1-Schalig | WI-LB | 0 | A | 3.75 | 1163HWa0812841137 | NEW | no | no | REI 60-A1 - D,s2-d0 /A1 | 0 | no |  | no | Codetext | AllplanAttributes - Ortscode_Geschoßbezeichnung: E01; ash_W_Trockenbau_Qualitäten: 9; Positionsnummer_Text: U100
 | H2 Ebene +1 | WI-LB | 1163Wa 0812841148 | yes | Codetext | m² | Trockenbauarbeiten | Wand | Innenwand 1-Schalig | WI-LB | 0 | A | 3.75 | 1163HWa0812841147 | NEW | no | no | REI 60-A1 - D,s2-d0 /A1 | 0 | no | 0 | no | Codetext | AllplanAttributes - Ortscode_Geschoßbezeichnung: E01; ash_W_Trockenbau_Qualitäten: 9; Positionsnummer_Text: U100
 | H2 Ebene +1 | WI-LB | 1163Wa 0812437332 | yes | Codetext | m² | Trockenbauarbeiten | Wand | Innenwand 1-Schalig | WI-LB | 0 | A | 3.75 | 1163HWa0812429063 | NEW | no | no | REI 60-A1 - D,s2-d0 /A1 | 0 | no | 0 | no | Codetext | AllplanAttributes - Ortscode_Geschoßbezeichnung: E01; W_Deckenanschluss: Gleitender Deckenanschluss Fall 01; ash_W_Trockenbau_Qualitäten: 13; Positionsnummer_Text: U100
 | H2 Ebene +1 | WI-LB | 1163Wa 0812841456 | yes | Codetext | m² | Trockenbauarbeiten | Wand | Innenwand 1-Schalig | WI-LB | 0 | A | 3.75 | 1163HWa0812841455 | NEW | no | no | REI 60-A1 - D,s2-d0 /A1 | 0 | no | 0 | no | Codetext | AllplanAttributes - Ortscode_Geschoßbezeichnung: E01; ash_W_Trockenbau_Qualitäten: 6; Positionsnummer_Text: U100
 | H2 Ebene +1 | WI-LB | 1163Wa 0812841599 | yes | Codetext | m² | Trockenbauarbeiten | Wand | Innenwand 1-Schalig | WI-LB | 0 | A | 3.75 | 1163HWa0812841598 | NEW | no | no | REI 60-A1 - D,s2-d0 /A1 | 0 | no | 0 | no | Codetext | AllplanAttributes - Ortscode_Geschoßbezeichnung: E01; ash_W_Trockenbau_Qualitäten: 9; Positionsnummer_Text: U100
 | H2 Ebene +1 | WI-LB | 1163Wa 0812841825 | yes | Codetext | m² | Trockenbauarbeiten | Wand | Innenwand 1-Schalig | WI-LB | 0 | A | 3.75 | 1163HWa0812841824 | NEW | no | no | REI 60-A1 - D,s2-d0 /A1 | 0 | no |  | no | Codetext | AllplanAttributes - Ortscode_Geschoßbezeichnung: E01; ash_W_Trockenbau_Qualitäten: 9; Positionsnummer_Text: U100
 | H2 Ebene +1 | WI-LB | 1163Wa 0812544546 | yes | Codetext | m² | Trockenbauarbeiten | Wand | Innenwand 1-Schalig | WI-LB | 0 | A | 3.75 | 1163HWa0812544521 | NEW |  | no | REI 60-A1 - D,s2-d0 /A1 | 0 | no | 0 | no | Codetext | AllplanAttributes - Ortscode_Geschoßbezeichnung: E01; W_Deckenanschluss: Gleitender Deckenanschluss Fall 01; ash_W_Trockenbau_Qualitäten: 13; Positionsnummer_Text: U100
 | H2 Ebene +1 | WI-LB | 1163Wa 0812842408 | yes | Codetext | m² | Trockenbauarbeiten | Wand | Innenwand 1-Schalig | WI-LB | 0 | A | 3.75 | 1163HWa0812842407 | NEW | no | no | REI 60-A1 - D,s2-d0 /A1 | 0 | no |  | no | Codetext | AllplanAttributes - Ortscode_Geschoßbezeichnung: E01; ash_W_Trockenbau_Qualitäten: 9; Positionsnummer_Text: U100
 | H2 Ebene +1 | WI-LB | 1163Wa 0812842430 | yes | Codetext | m² | Trockenbauarbeiten | Wand | Innenwand 1-Schalig | WI-LB | 0 | A | 3.75 | 1163HWa0812842429 | NEW | no | no | REI 60-A1 - D,s2-d0 /A1 | 0 | no |  | no | Codetext | AllplanAttributes - Ortscode_Geschoßbezeichnung: E01; ash_W_Trockenbau_Qualitäten: 9; Positionsnummer_Text: U100
 | H2 Ebene +1 | WI-LB | 1163Wa 0812846272 | yes | Codetext | m² | Trockenbauarbeiten | Wand | Innenwand 1-Schalig | WI-LB | 0 | A | 3.75 | 1163HWa0812846271 | NEW | no | no | REI 60-A1 - D,s2-d0 /A1 | 0 | no | 0 | no | Codetext | AllplanAttributes - Ortscode_Geschoßbezeichnung: E01; ash_W_Trockenbau_Qualitäten: 9; Positionsnummer_Text: U100
 | H2 Ebene +1 | WI-LB | 1163Wa 0812846432 | yes | Codetext | m² | Trockenbauarbeiten | Wand | Innenwand 1-Schalig | WI-LB | 0 | A | 3.75 | 1163HWa0812846431 | NEW | no | no | REI 60-A1 - D,s2-d0 /A1 | 0 | no | 0 | no | Codetext | AllplanAttributes - Ortscode_Geschoßbezeichnung: E01; ash_W_Trockenbau_Qualitäten: 9; Positionsnummer_Text: U100
 | H2 Ebene +1 | WI-LB | 1163Wa 0812447371 | yes | Codetext | m² | Trockenbauarbeiten | Wand | Innenwand 1-Schalig | WI-LB | 0 | A | 3.75 | 1163HWa0812429058 | NEW |  | no | 0 | 0 | no | 0 | no | Codetext | AllplanAttributes - Ortscode_Geschoßbezeichnung: E01; W_Deckenanschluss: Gleitender Deckenanschluss Fall 01; ash_W_Trockenbau_Qualitäten: 1; Positionsnummer_Text: U100
 | H2 Ebene +1 | WI-LB | 1163Wa 0813668651 | yes | Codetext | m² | Trockenbauarbeiten | Wand | Innenwand 1-Schalig | WI-LB | 0 | A | 3.75 | 1163HWa0813668650 | NEW |  | no | 0 | 0 | no | 0 | no | Codetext | AllplanAttributes - W_Deckenanschluss: Gleitender Deckenanschluss Fall 01; ash_W_Trockenbau_Qualitäten: 13; Positionsnummer_Text: U100
 | H2 Ebene +1 | WI-LB | 1163Wa 0812549302 | yes | Codetext | m² | Trockenbauarbeiten | Wand | Innenwand 1-Schalig | WI-LB | 0 | A | 3.75 | 1163HWa0812549295 | NEW | no | no | 0 | 0 | no | 0 | no | Codetext | AllplanAttributes - Ortscode_Geschoßbezeichnung: E01; W_Deckenanschluss: Gleitender Deckenanschluss Fall 01; ash_W_Trockenbau_Qualitäten: 1b; Positionsnummer_Text: U100
 | H2 Ebene +1 | WI-HW 60 | 1163Wa 0812551359 | yes | Codetext | m² | Zimmer- und Holzbauarbeiten | Wand | Innenwand 1-Schalig | WI-HW 60 | 0 | A | 3.75 | 1163HWa0812551344 | NEW | yes | no | REI 60-A1 - D,s2-d0 /A1 | 0 | no | 0 | no | Codetext | AllplanAttributes - Ortscode_Geschoßbezeichnung: E01; ash W_laufende Nr. Statik: 1 (W 1.0/ 1.1/ 1.2); Positionsnummer_Text: U100
 | H2 Ebene +1 | WI-HW 60 | 1163Wa 0812439829 | yes | Codetext | m² | Zimmer- und Holzbauarbeiten | Wand | Innenwand 1-Schalig | WI-HW 60 | 0 | A | 3.75 | 1163HWa0812439463 | NEW | yes | no | REI 60-A1 - D,s2-d0 +A1 | 0 | no | 0 | no | Codetext | AllplanAttributes - Ortscode_Geschoßbezeichnung: E01; ash W_laufende Nr. Statik: 3 (W 3.0); Positionsnummer_Text: U100
 | H2 Ebene +1 | WI-LB | 1163Wa 0812446171 |  | Codetext | m² | Trockenbauarbeiten | Wand |  |  | 0 | A | 3.75 | 1163HWa0812445210 | NEW | no | no | 0 | 0 | no | 0 | no | Codetext | AllplanAttributes - Ortscode_Geschoßbezeichnung: E01; W_Deckenanschluss: Gleitender Deckenanschluss Fall 03; ash_W_Trockenbau_Qualitäten: 10a; Positionsnummer_Text: U100
 | H2 Ebene +1 | WA-LB | 1163Wa 0813683984 | yes |  | m² | Trockenbauarbeiten | Wand | Außenwand 7-Schalig | WA-LB |  |  | 3.75 | 1163HWa0813683982 | NEW |  | yes | 0 | 0.9 |  | 32 | AllplanAttributes - Sicherheitsklasse: -; Sonnenschutztyp: Movable; g-Wert: 0,51; Positionsnummer_Text: U100
 | H2 Ebene +1 | WA-LB | 1163Wa 0813683985 | yes |  | m² | Trockenbauarbeiten | Wand | Außenwand 7-Schalig | WA-LB |  |  | 3.75 | 1163HWa0813683982 | NEW |  | yes | 0 | 0.9 |  | 32 | AllplanAttributes - Sicherheitsklasse: -; Sonnenschutztyp: Movable; g-Wert: 0,51; Positionsnummer_Text: U100
 | H2 Ebene +1 | WI-LB | 1163Wa 0812742684 | yes | Codetext | m² | Trockenbauarbeiten | Wand | Innenwand 1-Schalig | WI-LB | 0 | A | 3.75 | 1163HWa0812742683 | NEW | no | no | REI 60-A1 - D,s2-d0 /A1 | 0 | no | 0 | no | Codetext | AllplanAttributes - Ortscode_Geschoßbezeichnung: E01; W_Deckenanschluss: Gleitender Deckenanschluss Fall 01; ash_W_Trockenbau_Qualitäten: 1b; Positionsnummer_Text: U100
 | H2 Ebene +1 | WI-LB | 1163Wa 0812842178 | yes | Codetext | m² | Trockenbauarbeiten | Wand | Innenwand 1-Schalig | WI-LB | 0 | A | 3.75 | 1163HWa0812842177 | NEW | no | no | REI 60-A1 - D,s2-d0 /A1 | 0 | no |  | no | Codetext | AllplanAttributes - ash_W_Trockenbau_Qualitäten: 9; Positionsnummer_Text: U100
 | H2 Ebene +1 | WI-GKF | 1163Wa 0812834495 | yes | Codetext | m² | Trockenbauarbeiten | Wand | "BS-Beplankung; 2-fach Gipsfaserplatten" | WI-GKF | 0 | A | 3.75 | 1163HWa0812834487 | NEW | no | no | EI 60-A1 - D,s2,d0 +A1 | 0 | no | 0 | no | Codetext | AllplanAttributes - Ortscode_Geschoßbezeichnung: E01; Positionsnummer_Text: U100
 | H2 Ebene +1 | WI-GKF | 1163Wa 0812812558 | yes | Codetext | m² | Trockenbauarbeiten | Wand | "BS-Beplankung; 2-fach Gipsfaserplatten" | WI-GKF | 0 | A | 3.75 | 1163HWa0812812557 | NEW | no | no | EI 60-A1 - D,s2,d0 +A1 | 0 | no | 0 | no | Codetext | AllplanAttributes - Ortscode_Geschoßbezeichnung: E01; Positionsnummer_Text: U100
 | H2 Ebene +1 | WI-GKF | 1163Wa 0812812484 | yes | Codetext | m² | Trockenbauarbeiten | Wand | "BS-Beplankung; 2-fach Gipsfaserplatten" | WI-GKF | 0 | A | 3.75 | 1163HWa0812812483 | NEW | no | no | EI 60-A1 - D,s2,d0 +A1 | 0 | no | 0 | no | Codetext | AllplanAttributes - Ortscode_Geschoßbezeichnung: E01; Positionsnummer_Text: U100
 | H2 Ebene +1 | WI-GKF | 1163Wa 0812812539 | yes | Codetext | m² | Trockenbauarbeiten | Wand | "BS-Beplankung; 2-fach Gipsfaserplatten" | WI-GKF | 0 | A | 3.75 | 1163HWa0812812538 | NEW | no | no | EI 60-A1 - D,s2,d0 +A1 | 0 | no | 0 | no | Codetext | AllplanAttributes - Ortscode_Geschoßbezeichnung: E01; Positionsnummer_Text: U100
 | H2 Ebene +1 | WI-GKF | 1163Wa 0812834499 | yes | Codetext | m² | Trockenbauarbeiten | Wand | "BS-Beplankung; 2-fach Gipsfaserplatten" | WI-GKF | 0 | A | 3.75 | 1163HWa0812834485 | NEW | no | no | EI 60-A1 - D,s2,d0 +A1 | 0 | no | 0 | no | Codetext | AllplanAttributes - Ortscode_Geschoßbezeichnung: E01; Positionsnummer_Text: U100
 | H2 Ebene +1 | WI-GKF | 1163Wa 0812834493 | yes | Codetext | m² | Trockenbauarbeiten | Wand | "BS-Beplankung; 2-fach Gipsfaserplatten" | WI-GKF | 0 | A | 3.75 | 1163HWa0812834488 | NEW | no | no | EI 60-A1 - D,s2,d0 +A1 | 0 | no | 0 | no | Codetext | AllplanAttributes - Ortscode_Geschoßbezeichnung: E01; Positionsnummer_Text: U100
 | H2 Ebene +1 | WI-GKF | 1163Wa 0812834497 | yes | Codetext | m² | Trockenbauarbeiten | Wand | "BS-Beplankung; 2-fach Gipsfaserplatten" | WI-GKF | 0 | A | 3.75 | 1163HWa0812834483 | NEW | no | no | EI 60-A1 - D,s2,d0 +A1 | 0 | no | 0 | no | Codetext | AllplanAttributes - Ortscode_Geschoßbezeichnung: E01; Positionsnummer_Text: U100
 | H2 Ebene +1 | WI-GKF | 1163Wa 0812812465 | yes | Codetext | m² | Trockenbauarbeiten | Wand | "BS-Beplankung; 2-fach Gipsfaserplatten" | WI-GKF | 0 | A | 3.75 | 1163HWa0812812464 | NEW | no | no | EI 60-A1 - D,s2,d0 +A1 | 0 | no | 0 | no | Codetext | AllplanAttributes - Ortscode_Geschoßbezeichnung: E01; Positionsnummer_Text: U100
 | H2 Ebene +1 | WI-GKF | 1163Wa 0812812546 | yes | Codetext | m² | Trockenbauarbeiten | Wand | "BS-Beplankung; 2-fach Gipsfaserplatten" | WI-GKF | 0 | A | 3.75 | 1163HWa0812812545 | NEW | no | no | EI 60-A1 - D,s2,d0 +A1 | 0 | no | 0 | no | Codetext | AllplanAttributes - Ortscode_Geschoßbezeichnung: E01; Positionsnummer_Text: U100
 | H2 Ebene +1 | WI-GKF | 1163Wa 0812834492 | yes | Codetext | m² | Trockenbauarbeiten | Wand | "BS-Beplankung; 2-fach Gipsfaserplatten" | WI-GKF | 0 | A | 3.75 | 1163HWa0812834486 | NEW | no | no | EI 60-A1 - D,s2,d0 +A1 | 0 | no | 0 | no | Codetext | AllplanAttributes - Ortscode_Geschoßbezeichnung: E01; Positionsnummer_Text: U100
 | H2 Ebene +1 | WI-HW 60 | 1163Wa 0814148408 | yes | Codetext | m² | Zimmer- und Holzbauarbeiten | Wand | Innenwand 1-Schalig | WI-HW 60 | 0 | A | 3.75 | 1163HWa0813879184 | NEW | yes | no | REI 60-A1 - D,s2-d0 +A1 | 0 | no | 0 | no | Codetext | AllplanAttributes - ash W_laufende Nr. Statik: 3 (W 3.0); Positionsnummer_Text: U100
 | H2 Ebene +1 | WI-STB | 1163Wa 0812442412 | yes | Codetext | m² | Zimmer- und Holzbauarbeiten | Wand | Innenwand 1-Schalig | WI-STB | 0 | A | 3.75 | 1163HWa0812429187 | NEW | yes | no | REI 60-A1 - D,s2-d0 /A1 | 0 | no | 0 | no | Codetext | AllplanAttributes - Ortscode_Geschoßbezeichnung: E01; Positionsnummer_Text: U100
 | H2 Ebene +1 | WI-STB | 1163Wa 0812442409 | yes | Codetext | m² | Zimmer- und Holzbauarbeiten | Wand | Innenwand 1-Schalig | WI-STB | 0 | A | 3.75 | 1163HWa0812429185 | NEW | yes | no | REI 60-A1 - D,s2-d0 /A1 | 0 | no | 0 | no | Codetext | AllplanAttributes - Ortscode_Geschoßbezeichnung: E01; Positionsnummer_Text: U100
 | H2 Ebene +1 | WI-LB | 1163Wa 0813714683 | yes | Codetext | m² | Trockenbauarbeiten | Wand | Innenwand 1-Schalig | WI-LB | 0 | A | 3.75 | 1163HWa0813714672 | NEW | no | no | 0 | 0 | no | 47 | no | Codetext | AllplanAttributes - Ortscode_Geschoßbezeichnung: E01; W_Deckenanschluss: Gleitender Deckenanschluss Fall 01; ash_W_Trockenbau_Qualitäten: 1b; Positionsnummer_Text: U100
 | H2 Ebene +1 | WI-HW 60 | 1163Wa 0814184448 | yes | Codetext | m² | Zimmer- und Holzbauarbeiten | Wand | Innenwand 1-Schalig | WI-HW 60 | 0 | A | 3.75 | 1163HWa0812438661 | NEW | no | no | 0 | 0 | no |  | no | Codetext | AllplanAttributes - Sicherheitsklasse: -; Positionsnummer_Text: U100
 | H2 Ebene +1 | WI-HW 60 | 1163Wa 0812755264 | yes | Codetext | m² | Zimmer- und Holzbauarbeiten | Wand | Innenwand 1-Schalig | WI-HW 60 | 0 | A | 3.75 | 1163HWa0812755065 | NEW | yes | no | REI 60-A1 - D,s2-d0 +A1 | 0 | no | 47 | no | Codetext | AllplanAttributes - ash W_laufende Nr. Statik: 3 (W 3.0); Positionsnummer_Text: U100
 | H2 Ebene +1 | Installationsraum | 1163Wa 0813791910 | yes | Codetext | m² | Trockenbauarbeiten | Wand | Innenwand 1-Schalig | Installationsraum | 0 | A | 0 | 1113HWa0812434427 | NEW | no | no | 0 | 0 | no | 0 | no | Codetext | AllplanAttributes - Sicherheitsklasse: -; Positionsnummer_Text: U100
 | H2 Ebene +1 | WI-LB | 1163Wa 0814119770 | yes | Codetext | m² | Trockenbauarbeiten | Wand | Innenwand 1-Schalig | WI-LB | 0 | A | 3.75 | 1163HWa0812755065 | NEW | no | no | REI 60-A1 - D,s2-d0 /A1 | 0 | no | 0 | no | Codetext | AllplanAttributes - ash_W_Trockenbau_Qualitäten: 6; Positionsnummer_Text: U100
 | H2 Ebene +1 | WI-IW | 1163Wa 0813734405 | yes | Codetext | m² | Trockenbauarbeiten | Wand | Installationswand | WI-IW | 0 | A | 3.75 | 1163HWa0813734404 | NEW | no | no | 0 | 0 | no | 0 | no | Codetext | AllplanAttributes - Positionsnummer_Text: U100
 | H2 Ebene +1 | WI-IW | 1163Wa 0813734536 | yes | Codetext | m² | Trockenbauarbeiten | Wand | Installationswand | WI-IW | 0 | A | 3.75 | 1163HWa0813734535 | NEW | no | no | 0 | 0 | no | 52 | no | Codetext | AllplanAttributes - ash_W_Trockenbau_Qualitäten: 6; Positionsnummer_Text: U100
 | H2 Ebene +1 | WI-LB | 1163Wa 0814182446 | yes | Codetext | m² | Trockenbauarbeiten | Wand | Innenwand 1-Schalig | WI-LB | 0 | A | 3.75 | 1163HWa0812492424 | NEW | no | no | REI 30-A1 - D,s2-d0 +A1 | 0 | no | 47 | no | Codetext | AllplanAttributes - ash_W_Trockenbau_Qualitäten: 8; Sicherheitsklasse: -; Positionsnummer_Text: U100
 | H2 Ebene +1 | Installationsraum | 1163Wa 0814182445 | yes | Codetext | m² | Trockenbauarbeiten | Wand | Innenwand 1-Schalig | Installationsraum | 0 | A | 3.75 | 1163HWa0812492424 | NEW | no | no | 0 | 0 | no | 47 | no | Codetext | AllplanAttributes - Sicherheitsklasse: -; Positionsnummer_Text: U100
 | H2 Ebene +1 | WI-HW 60 | 1163Wa 0814182442 | yes | Codetext | m² | Zimmer- und Holzbauarbeiten | Wand | Innenwand 1-Schalig | WI-HW 60 | 0 | A | 3.75 | 1163HWa0812492424 | NEW | no | no | REI 30-A1 - D,s2-d0 +A1 | 0 | no | 47 | no | Codetext | AllplanAttributes - Sicherheitsklasse: -; ash W_laufende Nr. Statik: 3 (W 3.0); Positionsnummer_Text: U100
 | H2 Ebene +1 | WI-HW 60 | 1163Wa 0814179465 | yes | Codetext | m² | Zimmer- und Holzbauarbeiten | Wand | Innenwand 1-Schalig | WI-HW 60 | 0 | A | 3.75 | 1163HWa0812492424 | NEW | no | no | REI 30-A1 - D,s2-d0 +A1 | 0 | no | 47 | no | Codetext | AllplanAttributes - Sicherheitsklasse: -; Positionsnummer_Text: U100
 | H2 Ebene +1 | WI-LB | 1163Wa 0812842672 | yes | Codetext | m² | Trockenbauarbeiten | Wand | Innenwand 1-Schalig | WI-LB | 0 | A | 3.75 | 1163HWa0812842671 | NEW | no | no | REI 60-A1 - D,s2-d0 /A1 | 0 | no | 0 | no | Codetext | AllplanAttributes - ash_W_Trockenbau_Qualitäten: 6; Positionsnummer_Text: U100
 | H2 Ebene +1 | WI-LB | 1163Wa 0812842684 | yes | Codetext | m² | Trockenbauarbeiten | Wand | Innenwand 1-Schalig | WI-LB | 0 | A | 3.75 | 1163HWa0812842683 | NEW | no | no | REI 60-A1 - D,s2-d0 /A1 | 0 | no | 0 | no | Codetext | AllplanAttributes - ash_W_Trockenbau_Qualitäten: 6; Positionsnummer_Text: U100
 | H2 Ebene +1 | WI-STB | 1163Wa 0812442421 | yes | Codetext | m² | Zimmer- und Holzbauarbeiten | Wand | Innenwand 1-Schalig | WI-STB | 0 | A | 3.75 | 1163HWa0812434911 | NEW | yes | no | REI 60-A1 - D,s2-d0 /A1 | 0 | no | 0 | no | Codetext | AllplanAttributes - Positionsnummer_Text: U100
 | H2 Ebene +1 | WI-LB | 1163Wa 0812842557 | yes | Codetext | m² | Trockenbauarbeiten | Wand | Innenwand 1-Schalig | WI-LB | 0 | A | 3.75 | 1163HWa0812842556 | NEW | no | no | REI 60-A1 - D,s2-d0 /A1 | 0 | no | 0 | no | Codetext | AllplanAttributes - ash_W_Trockenbau_Qualitäten: 9; Positionsnummer_Text: U100
 | H2 Ebene +1 | WI-LB | 1163Wa 0812842569 | yes | Codetext | m² | Trockenbauarbeiten | Wand | Innenwand 1-Schalig | WI-LB | 0 | A | 3.75 | 1163HWa0812842568 | NEW | no | no | REI 60-A1 - D,s2-d0 /A1 | 0 | no | 0 | no | Codetext | AllplanAttributes - ash_W_Trockenbau_Qualitäten: 6; Positionsnummer_Text: U100
 | H2 Ebene +1 | WI-HW 60 | 1163Wa 0812443013 | yes | Codetext | m² | Zimmer- und Holzbauarbeiten | Wand | Innenwand 1-Schalig | WI-HW 60 | 0 | A | 3.75 | 1163HWa0812440742 | NEW | yes | no | REI 60-A1 - D,s2-d0 +A1 | 0 | no | 0 | no | Codetext | AllplanAttributes - Ortscode_Geschoßbezeichnung: E01; ash W_laufende Nr. Statik: 3 (W 3.0); Positionsnummer_Text: U100
 | H2 Ebene +1 | WI-HW 60 | 1163Wa 0812442406 | yes |  | m² | Zimmer- und Holzbauarbeiten | Wand | Innenwand 1-Schalig | WI-HW 60 |  |  | 3.75 | 1163HWa0812430471 | NEW | yes | no | REI-M 60-D,s2,d0 + A1 | AllplanAttributes - ash W_laufende Nr. Statik: 7 (W 6.0-1); Positionsnummer_Text: U100
 | H2 Ebene +1 | WI-LB | 1163Wa 0812440282 | yes | Codetext | m² | Trockenbauarbeiten | Wand | Innenwand 1-Schalig | WI-LB | 0 | A | 3.75 | 1163HWa0812438500 | NEW | no | no | REI 60-A1 - D,s2-d0 /A1 | 0 | no | 0 | no | Codetext | AllplanAttributes - Positionsnummer_Text: U100
 | H2 Ebene +1 | WI-HW 60 | 1163Wa 0813788458 | yes | Codetext | m² | Zimmer- und Holzbauarbeiten | Wand | Innenwand 1-Schalig | WI-HW 60 | 0 | A | 3.75 | 1163HWa0812438500 | NEW | yes | no | REI 60-A1 - D,s2-d0 +A1 | 0 | no | 0 | no | Codetext | AllplanAttributes - ash W_laufende Nr. Statik: 3 (W 3.0); Positionsnummer_Text: U100
 | H2 Ebene +1 | WI-LB | 1163Wa 0812440284 | yes | Codetext | m² | Trockenbauarbeiten | Wand | Innenwand 1-Schalig | WI-LB | 0 | A | 3.75 | 1163HWa0812438506 | NEW | no | no | 0 | 0 | no | 0 | no | Codetext | AllplanAttributes - Sicherheitsklasse: -; Positionsnummer_Text: U100
 | H2 Ebene +1 | WI-HW 60 | 1163Wa 0813788420 | yes | Codetext | m² | Zimmer- und Holzbauarbeiten | Wand | Innenwand 1-Schalig | WI-HW 60 | 0 | A | 3.75 | 1163HWa0812438506 | NEW | no | no | 0 | 0 | no | 0 | no | Codetext | AllplanAttributes - Sicherheitsklasse: -; ash W_laufende Nr. Statik: 3 (W 3.0); Positionsnummer_Text: U100
 | H2 Ebene +1 | WI-STB | 1163Wa 0812852060 | yes | Codetext | m² | Zimmer- und Holzbauarbeiten | Wand | Innenwand 1-Schalig | WI-STB | 0 | A | 3.75 | 1163HWa0812851836 | NEW | yes | no | REI 60-A1 - D,s2-d0 /A1 | 0 | no | 0 | no | Codetext | AllplanAttributes - Positionsnummer_Text: U100
 | H2 Ebene +1 | WI-STB | 1163Wa 0812542171 | yes | Codetext | m² | Zimmer- und Holzbauarbeiten | Wand | Außenwand 1-Schalig | WI-STB | 0 | A | 3.75 | 1163HWa0812542150 | NEW | yes | no | REI 60-A1 - D,s2-d0 /A1 | 0 | no | 0 | no | Codetext | AllplanAttributes - Ortscode_Geschoßbezeichnung: E01; Positionsnummer_Text: U100
 | H2 Ebene +1 | WI-STB | 1163Wa 0812755800 | yes | Codetext | m² | Zimmer- und Holzbauarbeiten | Wand | Außenwand 1-Schalig | WI-STB | 0 | A | 3.75 | 1163HWa0812755799 | NEW | yes | no | REI 60-A1 - D,s2-d0 /A1 | 0 | no | 52 | no | Codetext | AllplanAttributes - Ortscode_Geschoßbezeichnung: E01; Positionsnummer_Text: U100
 | H2 Ebene +1 | WI-LB | 1163Wa 0812841723 | yes | Codetext | m² | Trockenbauarbeiten | Wand | Außenwand 1-Schalig | WI-LB | 0 | A | 3.75 | 1163HWa0812755799 | NEW | no | no | REI 60-A1 - D,s2-d0 /A1 | 0 | no |  | no | Codetext | AllplanAttributes - Ortscode_Geschoßbezeichnung: E01; ash_W_Trockenbau_Qualitäten: 9; Positionsnummer_Text: U100
 | H2 Ebene +1 | WI-STB | 1163Wa 0812544542 | yes | Codetext | m² | Zimmer- und Holzbauarbeiten | Wand | Außenwand 1-Schalig | WI-STB | 0 | A | 3.75 | 1163HWa0812544533 | NEW | yes | no | REI 60-A1 - D,s2-d0 /A1 | 0 | no | 52 | no | Codetext | AllplanAttributes - Ortscode_Geschoßbezeichnung: E01; Positionsnummer_Text: U100
 | H2 Ebene +1 | WI-LB | 1163Wa 0812841636 | yes | Codetext | m² | Trockenbauarbeiten | Wand | Außenwand 1-Schalig | WI-LB | 0 | A | 3.75 | 1163HWa0812544533 | NEW | no | no | REI 60-A1 - D,s2-d0 /A1 | 0 | no |  | no | Codetext | AllplanAttributes - Ortscode_Geschoßbezeichnung: E01; ash_W_Trockenbau_Qualitäten: 9; Positionsnummer_Text: U100
 | H2 Ebene +1 | WI-STB | 1163Wa 0812543042 | yes | Codetext | m² | Zimmer- und Holzbauarbeiten | Wand | Außenwand 1-Schalig | WI-STB | 0 | A | 3.75 | 1163HWa0812543031 | NEW | yes | no | REI 60-A1 - D,s2-d0 /A1 | 0 | no | 0 | no | Codetext | AllplanAttributes - Ortscode_Geschoßbezeichnung: E01; Positionsnummer_Text: U100
 | H2 Ebene +1 | WI-STB | 1163Wa 0812440543 | yes | Codetext | m² | Zimmer- und Holzbauarbeiten | Wand | Außenwand 1-Schalig | WI-STB | 0 | A | 3.75 | 1163HWa0812430779 | NEW | yes | no | REI 60-A1 - D,s2-d0 /A1 | 0 | no | 52 | no | Codetext | AllplanAttributes - Ortscode_Geschoßbezeichnung: E01; Positionsnummer_Text: U100
 | H2 Ebene +1 | WI-STB | 1163Wa 0812442083 | yes | Codetext | m² | Zimmer- und Holzbauarbeiten | Wand | Außenwand 1-Schalig | WI-STB | 0 | A | 3.75 | 1163HWa0812430777 | NEW | yes | no | REI 60-A1 - D,s2-d0 /A1 | 0 | no | 52 | no | Codetext | AllplanAttributes - Ortscode_Geschoßbezeichnung: E01; Positionsnummer_Text: U100
 | H2 Ebene +1 | WI-STB | 1163Wa 0812542416 | yes | Codetext | m² | Zimmer- und Holzbauarbeiten | Wand | Außenwand 1-Schalig | WI-STB | 0 | A | 3.75 | 1163HWa0812542404 | NEW | yes | no | REI 60-A1 - D,s2-d0 /A1 | 0 | no | 47 | no | Codetext | AllplanAttributes - Ortscode_Geschoßbezeichnung: E01; Positionsnummer_Text: U100
 | H2 Ebene +1 | WI-STB | 1163Wa 0812542413 | yes | Codetext | m² | Zimmer- und Holzbauarbeiten | Wand | Außenwand 1-Schalig | WI-STB | 0 | A | 3.75 | 1163HWa0812542407 | NEW | yes | no | REI 60-A1 - D,s2-d0 /A1 | 0 | no | 47 | no | Codetext | AllplanAttributes - Ortscode_Geschoßbezeichnung: E01; Positionsnummer_Text: U100
 | H2 Ebene +1 | WI-HW 60 | 1163Wa 0812447125 | yes | Codetext | m² | Zimmer- und Holzbauarbeiten | Wand | Innenwand 1-Schalig | WI-HW 60 | 0 | A | 3.75 | 1163HWa0812434680 | NEW | yes | no | REI 60-A1 - D,s2-d0 +A1 | 0 | no | 52 | no | Codetext | AllplanAttributes - Ortscode_Geschoßbezeichnung: E01; ash W_laufende Nr. Statik: 3 (W 3.0); Positionsnummer_Text: U100
 | H2 Ebene +1 | WI-HW 60 | 1163Wa 0812446819 | yes |  | m² | Zimmer- und Holzbauarbeiten | Wand | Innenwand 1-Schalig | WI-HW 60 |  |  | 3.75 | 1163HWa0812435298 | NEW | yes | no | REI-M 60-D,s2,d0 + A1 |  |  | 47 | AllplanAttributes - ash W_laufende Nr. Statik: 7 (W 6.0-1); Positionsnummer_Text: U100
 | H2 Ebene +1 | WI-LB | 1163Wa 0812446048 |  | Codetext | m² | Trockenbauarbeiten | Wand |  |  | 0 | A | 3.75 | 1163HWa0812425469 | NEW |  | no | 0 | 0 | no | 47 | no | Codetext | AllplanAttributes - Ortscode_Geschoßbezeichnung: E01; W_Deckenanschluss: Gleitender Deckenanschluss Fall 03; ash_W_Trockenbau_Qualitäten: 1c; Positionsnummer_Text: U100
 | H2 Ebene +1 | WI-LB | 1163Wa 0812446046 |  | Codetext | m² | Trockenbauarbeiten | Wand |  |  | 0 | A | 3.75 | 1163HWa0812425472 | NEW |  | no | 0 | 0 | no | 47 | no | Codetext | AllplanAttributes - Ortscode_Geschoßbezeichnung: E01; W_Deckenanschluss: Gleitender Deckenanschluss Fall 03; ash_W_Trockenbau_Qualitäten: 1c; Positionsnummer_Text: U100
 | H2 Ebene +1 | WI-LB | 1163Wa 0812439308 |  | Codetext | m² | Trockenbauarbeiten | Wand | Innenwand 1-Schalig | WI-LB | 0 | A | 3.75 | 1163HWa0812425479 | NEW |  | no | REI 30 | 0 | no | 47 | no | Codetext | AllplanAttributes - Ortscode_Geschoßbezeichnung: E01; W_Deckenanschluss: Gleitender Deckenanschluss Fall 03; ash_W_Trockenbau_Qualitäten: 1c; Positionsnummer_Text: U100
 | H2 Ebene +1 | WI-LB | 1163Wa 0812438264 |  | Codetext | m² | Trockenbauarbeiten | Wand | Innenwand 1-Schalig | WI-LB | 0 | A | 3.75 | 1163HWa0812425560 | NEW |  | no | REI 30 | 0 | no | 47 | no | Codetext | AllplanAttributes - Ortscode_Geschoßbezeichnung: E01; W_Deckenanschluss: Gleitender Deckenanschluss Fall 03; ash_W_Trockenbau_Qualitäten: 1c; Positionsnummer_Text: U100
 | H2 Ebene +1 | WI-LB | 1163Wa 0812438997 |  | Codetext | m² | Trockenbauarbeiten | Wand |  |  | 0 | A | 3.75 | 1163HWa0812425571 | NEW |  | no | 0 | 0 | no | 47 | no | Codetext | AllplanAttributes - Ortscode_Geschoßbezeichnung: E01; W_Deckenanschluss: Gleitender Deckenanschluss Fall 03; ash_W_Trockenbau_Qualitäten: 1c; Positionsnummer_Text: U100
 | H2 Ebene +1 | WI-LB | 1163Wa 0812438278 |  | Codetext | m² | Trockenbauarbeiten | Wand | Innenwand 1-Schalig | WI-LB | 0 | A | 3.75 | 1163HWa0812435113 | NEW |  | no | REI 30 | 0 | no | 47 | no | Codetext | AllplanAttributes - Ortscode_Geschoßbezeichnung: E01; W_Deckenanschluss: Gleitender Deckenanschluss Fall 03; ash_W_Trockenbau_Qualitäten: 1c; Positionsnummer_Text: U100
 | H2 Ebene +1 | WI-LB | 1163Wa 0812437675 |  | Codetext | m² | Trockenbauarbeiten | Wand |  |  | 0 | A | 3.75 | 1163HWa0812425538 | NEW |  | no | 0 | 0 | no | 47 | no | Codetext | AllplanAttributes - Ortscode_Geschoßbezeichnung: E01; W_Deckenanschluss: Gleitender Deckenanschluss Fall 03; ash_W_Trockenbau_Qualitäten: 1c; Positionsnummer_Text: U100
 | H2 Ebene +1 | WI-LB | 1163Wa 0812437673 |  | Codetext | m² | Trockenbauarbeiten | Wand |  |  | 0 | A | 3.75 | 1163HWa0812425551 | NEW |  | no | 0 | 0 | no | 47 | no | Codetext | AllplanAttributes - Ortscode_Geschoßbezeichnung: E01; W_Deckenanschluss: Gleitender Deckenanschluss Fall 03; ash_W_Trockenbau_Qualitäten: 1c; Positionsnummer_Text: U100
 | H2 Ebene +1 | WI-LB | 1163Wa 0812437677 |  | Codetext | m² | Trockenbauarbeiten | Wand |  |  | 0 | A | 3.75 | 1163HWa0812425533 | NEW |  | no | 0 | 0 | no | 47 | no | Codetext | AllplanAttributes - Ortscode_Geschoßbezeichnung: E01; W_Deckenanschluss: Gleitender Deckenanschluss Fall 03; ash_W_Trockenbau_Qualitäten: 1c; Positionsnummer_Text: U100
 | H2 Ebene +1 | WI-LB | 1163Wa 0812439304 |  | Codetext | m² | Trockenbauarbeiten | Wand | Innenwand 1-Schalig | WI-LB | 0 | A | 3.75 | 1163HWa0812425510 | NEW |  | no | REI 30 | 0 | no | 47 | no | Codetext | AllplanAttributes - Ortscode_Geschoßbezeichnung: E01; W_Deckenanschluss: Gleitender Deckenanschluss Fall 03; ash_W_Trockenbau_Qualitäten: 1c; Positionsnummer_Text: U100
 | H2 Ebene +1 | WI-LB | 1163Wa 0812438999 |  | Codetext | m² | Trockenbauarbeiten | Wand |  |  | 0 | A | 3.75 | 1163HWa0812425505 | NEW |  | no | 0 | 0 | no | 47 | no | Codetext | AllplanAttributes - Ortscode_Geschoßbezeichnung: E01; W_Deckenanschluss: Gleitender Deckenanschluss Fall 03; ash_W_Trockenbau_Qualitäten: 1c; Positionsnummer_Text: U100
 | H2 Ebene +1 | WI-LB | 1163Wa 0812439001 |  | Codetext | m² | Trockenbauarbeiten | Wand |  |  | 0 | A | 3.75 | 1163HWa0812425497 | NEW |  | no | 0 | 0 | no | 47 | no | Codetext | AllplanAttributes - Ortscode_Geschoßbezeichnung: E01; W_Deckenanschluss: Gleitender Deckenanschluss Fall 03; ash_W_Trockenbau_Qualitäten: 1c; Positionsnummer_Text: U100
 | H2 Ebene +1 | WI-LB | 1163Wa 0812446199 |  | Codetext | m² | Trockenbauarbeiten | Wand | Innenwand 1-Schalig | WI-LB | 0 | A | 3.75 | 1163HWa0812425471 | NEW |  | no | REI 30 | 0 | no | 47 | no | Codetext | AllplanAttributes - Ortscode_Geschoßbezeichnung: E01; W_Deckenanschluss: Gleitender Deckenanschluss Fall 03; ash_W_Trockenbau_Qualitäten: 1c; Positionsnummer_Text: U100
 | H2 Ebene +1 | WI-LB | 1163Wa 0812446145 |  | Codetext | m² | Trockenbauarbeiten | Wand | Innenwand 1-Schalig | WI-LB | 0 | A | 3.75 | 1163HWa0812425468 | NEW |  | no | REI 30 | 0 | no | 47 | no | Codetext | AllplanAttributes - Ortscode_Geschoßbezeichnung: E01; W_Deckenanschluss: Gleitender Deckenanschluss Fall 03; ash_W_Trockenbau_Qualitäten: 1c; Positionsnummer_Text: U100
 | H2 Ebene +1 | WI-LB | 1163Wa 0812446716 |  | Codetext | m² | Trockenbauarbeiten | Wand | Innenwand 1-Schalig | WI-LB | 0 | A | 3.75 | 1163HWa0812425474 | NEW |  | no | REI 30 | 0 | no | 47 | no | Codetext | AllplanAttributes - Ortscode_Geschoßbezeichnung: E01; W_Deckenanschluss: Gleitender Deckenanschluss Fall 03; ash_W_Trockenbau_Qualitäten: 1c; Positionsnummer_Text: U100
 | H2 Ebene +1 | WI-HW 60 | 1163Wa 0812447407 | yes |  | m² | Zimmer- und Holzbauarbeiten | Wand | Innenwand 1-Schalig | WI-HW 60 |  |  | 3.75 | 1163HWa0812435124 | NEW | yes | no | REI-M 60-D,s2,d0 + A1 |  |  | 42 | AllplanAttributes - ash W_laufende Nr. Statik: 7 (W 6.0-1); Positionsnummer_Text: U100
 | H2 Ebene +1 | WI-HW 60 | 1163Wa 0812533137 | yes |  | m² | Zimmer- und Holzbauarbeiten | Wand | Innenwand 1-Schalig | WI-HW 60 |  |  | 3.75 | 1163HWa0812533119 | NEW | yes | no | REI-M 60-D,s2,d0 + A1 |  |  | 52 | AllplanAttributes - ash W_laufende Nr. Statik: 7 (W 6.0-1); Positionsnummer_Text: U100
 | H2 Ebene +1 | WI-LB | 1163Wa 0812444136 | yes | Codetext | m² | Trockenbauarbeiten | Wand | Innenwand 1-Schalig | WI-LB | 0 | A | 3.75 | 1163HWa0812443700 | NEW | no | no | REI 60-A1 - D,s2-d0 +A1 | 0 | no | 47 | no | Codetext | AllplanAttributes - Ortscode_Geschoßbezeichnung: E01; W_Deckenanschluss: Gleitender Deckenanschluss Fall 01; ash_W_Trockenbau_Qualitäten: 1b; Positionsnummer_Text: U100
 | H2 Ebene +1 | WI-LB | 1163Wa 0812437253 | yes | Codetext | m² | Trockenbauarbeiten | Wand | Innenwand 1-Schalig | WI-LB | 0 | A | 3.75 | 1163HWa0812435324 | NEW |  | no | 0 | 0 | no | 47 | no | Codetext | AllplanAttributes - Ortscode_Geschoßbezeichnung: E01; W_Deckenanschluss: Gleitender Deckenanschluss Fall 01; ash_W_Trockenbau_Qualitäten: 1b; Positionsnummer_Text: U100
 | H2 Ebene +1 | WI-LB | 1163Wa 0812438796 | yes | Codetext | m² | Trockenbauarbeiten | Wand | Innenwand 1-Schalig | WI-LB | 0 | A | 3.75 | 1163HWa0812438777 | NEW |  | no | 0 | 0 | no | 47 | no | Codetext | AllplanAttributes - Ortscode_Geschoßbezeichnung: E01; W_Deckenanschluss: Gleitender Deckenanschluss Fall 01; ash_W_Trockenbau_Qualitäten: 1b; Positionsnummer_Text: U100
 | H2 Ebene +1 | WI-LB | 1163Wa 0812437356 | yes | Codetext | m² | Trockenbauarbeiten | Wand | Innenwand 1-Schalig | WI-LB | 0 | A | 3.75 | 1163HWa0812425466 | NEW | no | no | 0 | 0 | no | 47 | no | Codetext | AllplanAttributes - Ortscode_Geschoßbezeichnung: E01; W_Deckenanschluss: Gleitender Deckenanschluss Fall 01; ash_W_Trockenbau_Qualitäten: 1; Positionsnummer_Text: U100
 | H2 Ebene +1 | WI-LB | 1163Wa 0812437369 | yes | Codetext | m² | Trockenbauarbeiten | Wand | Innenwand 1-Schalig | WI-LB | 0 | A | 3.75 | 1163HWa0812425465 | NEW | no | no | 0 | 0 | no | 47 | no | Codetext | AllplanAttributes - Ortscode_Geschoßbezeichnung: E01; W_Deckenanschluss: Gleitender Deckenanschluss Fall 01; ash_W_Trockenbau_Qualitäten: 1b; Positionsnummer_Text: U100
 | H2 Ebene +1 | WI-LB | 1163Wa 0812532030 | yes | Codetext | m² | Trockenbauarbeiten | Wand | Innenwand 1-Schalig | WI-LB | 0 | A | 3.75 | 1163HWa0812532027 | NEW | no | no | 0 | 0 | no | 42 | no | Codetext | AllplanAttributes - W_Deckenanschluss: Gleitender Deckenanschluss Fall 03; ash_W_Trockenbau_Qualitäten: 1; Positionsnummer_Text: U100
 | H2 Ebene +1 | WI-HW 60 | 1163Wa 0812499133 | yes | Codetext | m² | Zimmer- und Holzbauarbeiten | Wand | Innenwand 1-Schalig | WI-HW 60 | 0 | A | 3.75 | 1163HWa0812499131 | NEW | no | no | 0 | 0 | no | 47 | no | Codetext | AllplanAttributes - Sicherheitsklasse: -; ash W_laufende Nr. Statik: 3 (W 3.0); Positionsnummer_Text: U100
 | H2 Ebene +1 | WI-LB | 1163Wa 0813782270 | yes | Codetext | m² | Trockenbauarbeiten | Wand | Innenwand 1-Schalig | WI-LB | 0 | A | 3.75 | 1163HWa0812499131 | NEW | no | no | 0 | 0 | no | 47 | no | Codetext | AllplanAttributes - ash_W_Trockenbau_Qualitäten: 6; Sicherheitsklasse: -; Positionsnummer_Text: U100
 | H2 Ebene +1 | WI-HW 60 | 1163Wa 0812444104 | yes | Codetext | m² | Zimmer- und Holzbauarbeiten | Wand | Innenwand 1-Schalig | WI-HW 60 | 0 | A | 3.75 | 1163HWa0812434275 | NEW | yes | no | REI 60-A1 - D,s2-d0 +A1 | 0 | no | 47 | no | Codetext | AllplanAttributes - ash W_laufende Nr. Statik: 3 (W 3.0); Positionsnummer_Text: U100
 | H2 Ebene +1 | WI-LB | 1163Wa 0813781658 | yes | Codetext | m² | Trockenbauarbeiten | Wand | Innenwand 1-Schalig | WI-LB | 0 | A | 3.75 | 1163HWa0812434275 | NEW | no | no | REI 60-A1 - D,s2-d0 /A1 | 0 | no | 47 | no | Codetext | AllplanAttributes - ash_W_Trockenbau_Qualitäten: 6; Positionsnummer_Text: U100
 | H2 Ebene +1 | WI-HW 60 | 1163Wa 0812447107 | yes | Codetext | m² | Zimmer- und Holzbauarbeiten | Wand | Innenwand 1-Schalig | WI-HW 60 | 0 | A | 3.75 | 1163HWa0812434283 | NEW | yes | no | REI 60-A1 - D,s2-d0 +A1 | 0 | no | 52 | no | Codetext | AllplanAttributes - ash W_laufende Nr. Statik: 3 (W 3.0); Positionsnummer_Text: U100
 | H2 Ebene +1 | WI-LB | 1163Wa 0813785915 | yes | Codetext | m² | Trockenbauarbeiten | Wand | Innenwand 1-Schalig | WI-LB | 0 | A | 3.75 | 1163HWa0812434283 | NEW | no | no | REI 60-A1 - D,s2-d0 /A1 | 0 | no | 52 | no | Codetext | AllplanAttributes - ash_W_Trockenbau_Qualitäten: 6; Positionsnummer_Text: U100
 | H2 Ebene +1 | WI-HW 60 | 1163Wa 0812439595 | yes | Codetext | m² | Zimmer- und Holzbauarbeiten | Wand | Innenwand 1-Schalig | WI-HW 60 | 0 | A | 3.75 | 1163HWa0812430479 | NEW | no | no | 0 | 0 | no | 52 | no | Codetext | AllplanAttributes - Sicherheitsklasse: -; ash W_laufende Nr. Statik: 3 (W 3.0); Positionsnummer_Text: U100
 | H2 Ebene +1 | Installationsraum | 1163Wa 0813786687 | yes | Codetext | m² | Trockenbauarbeiten | Wand | Innenwand 1-Schalig | Installationsraum | 0 | A | 3.75 | 1163HWa0812430479 | NEW | no | no | 0 | 0 | no | 0 | no | Codetext | AllplanAttributes - Sicherheitsklasse: -; Positionsnummer_Text: U100
 | H2 Ebene +1 | WI-LB | 1163Wa 0814104635 | yes | Codetext | m² | Trockenbauarbeiten | Wand | Innenwand 1-Schalig | WI-LB | 0 | A | 3.75 | 1163HWa0812430479 | NEW | no | no | 0 | 0 | no | 52 | no | Codetext | AllplanAttributes - ash_W_Trockenbau_Qualitäten: 8; Sicherheitsklasse: -; Positionsnummer_Text: U100
 | H2 Ebene +1 | WI-HW 60 | 1163Wa 0812774550 | yes | Codetext | m² | Zimmer- und Holzbauarbeiten | Wand | Innenwand 1-Schalig | WI-HW 60 | 0 | A | 3.75 | 1163HWa0812774549 | NEW | no | no | 0 | 0 | no | 47 | no | Codetext | AllplanAttributes - ash W_laufende Nr. Statik: 3 (W 3.0); Positionsnummer_Text: U100
 | H2 Ebene +1 | Installationsraum | 1163Wa 0813786979 | yes | Codetext | m² | Trockenbauarbeiten | Wand | Innenwand 1-Schalig | Installationsraum | 0 | A | 3.75 | 1163HWa0812774549 | NEW | no | no | 0 | 0 | no | 47 | no | Codetext | AllplanAttributes - Positionsnummer_Text: U100
 | H2 Ebene +1 | WI-LB | 1163Wa 0813787154 | yes | Codetext | m² | Trockenbauarbeiten | Wand | Innenwand 1-Schalig | WI-LB | 0 | A | 3.75 | 1163HWa0812774549 | NEW | no | no | 0 | 0 | no | 47 | no | Codetext | AllplanAttributes - ash_W_Trockenbau_Qualitäten: 8; Sicherheitsklasse: -; Positionsnummer_Text: U100
 | H2 Ebene +1 | WI-LB | 1163Wa 0812437318 | yes | Codetext | m² | Trockenbauarbeiten | Wand | Innenwand 1-Schalig | WI-LB | 0 | A | 3.75 | 1163HWa0812434265 | NEW | no | no | REI 60-A1 - D,s2-d0 /A1 | 0 | no | 52 | no | Codetext | AllplanAttributes - ash_W_Trockenbau_Qualitäten: 6; Positionsnummer_Text: U100
 | H2 Ebene +1 | WI-HW 60 | 1163Wa 0813784997 | yes | Codetext | m² | Zimmer- und Holzbauarbeiten | Wand | Innenwand 1-Schalig | WI-HW 60 | 0 | A | 3.75 | 1163HWa0812434265 | NEW | yes | no | REI 60-A1 - D,s2-d0 +A1 | 0 | no | 52 | no | Codetext | AllplanAttributes - ash W_laufende Nr. Statik: 3 (W 3.0); Positionsnummer_Text: U100
 | H2 Ebene +1 | WI-LB | 1163Wa 0812446823 | yes | Codetext | m² | Trockenbauarbeiten | Wand | Innenwand 1-Schalig | WI-LB | 0 | A | 3.75 | 1163HWa0812430886 | NEW | no | no | 0 | 0 | no | 47 | no | Codetext | AllplanAttributes - ash_W_Trockenbau_Qualitäten: 8; Sicherheitsklasse: -; Positionsnummer_Text: U100
 | H2 Ebene +1 | Installationsraum | 1163Wa 0813784241 | yes | Codetext | m² | Trockenbauarbeiten | Wand | Innenwand 1-Schalig | Installationsraum | 0 | A | 3.75 | 1163HWa0812430886 | NEW | no | no | 0 | 0 | no | 47 | no | Codetext | AllplanAttributes - Positionsnummer_Text: U100
 | H2 Ebene +1 | WI-HW 60 | 1163Wa 0813784428 | yes | Codetext | m² | Zimmer- und Holzbauarbeiten | Wand | Innenwand 1-Schalig | WI-HW 60 | 0 | A | 3.75 | 1163HWa0812430886 | NEW | no | no | 0 | 0 | no | 47 | no | Codetext | AllplanAttributes - ash W_laufende Nr. Statik: 3 (W 3.0); Positionsnummer_Text: U100
 | H2 Ebene +1 | WI-LB | 1163Wa 0812543262 | yes | Codetext | m² | Trockenbauarbeiten | Wand | Innenwand 1-Schalig | WI-LB | 0 | A | 3.75 | 1163HWa0812543150 | NEW | no | no | REI 60-A1 - D,s2-d0 /A1 | 0 | no | 52 | no | Codetext | AllplanAttributes - ash_W_Trockenbau_Qualitäten: 6; Positionsnummer_Text: U100
 | H2 Ebene +1 | Installationsraum | 1163Wa 0813786056 | yes | Codetext | m² | Trockenbauarbeiten | Wand | Innenwand 1-Schalig | Installationsraum | 0 | A | 3.75 | 1163HWa0812543150 | NEW | no | no | 0 | 0 | no | 52 | no | Codetext | AllplanAttributes - Positionsnummer_Text: U100
 | H2 Ebene +1 | WI-HW 60 | 1163Wa 0813786057 | yes | Codetext | m² | Zimmer- und Holzbauarbeiten | Wand | Innenwand 1-Schalig | WI-HW 60 | 0 | A | 3.75 | 1163HWa0812543150 | NEW | no | no | REI 60-A1 - D,s2-d0 +A1 | 0 | no | 52 | no | Codetext | AllplanAttributes - ash W_laufende Nr. Statik: 3 (W 3.0); Positionsnummer_Text: U100
 | H2 Ebene +1 | WI-LB | 1163Wa 0812447441 | yes | Codetext | m² | Trockenbauarbeiten | Wand | Innenwand 1-Schalig | WI-LB | 0 | A | 3.75 | 1163HWa0812438083 | NEW | no | no | 0 | 0 | no | 52 | no | Codetext | AllplanAttributes - ash_W_Trockenbau_Qualitäten: 8; Sicherheitsklasse: -; Positionsnummer_Text: U100
 | H2 Ebene +1 | Installationsraum | 1163Wa 0813786483 | yes | Codetext | m² | Trockenbauarbeiten | Wand | Innenwand 1-Schalig | Installationsraum | 0 | A | 3.75 | 1163HWa0812438083 | NEW | no | no | 0 | 0 | no | 52 | no | Codetext | AllplanAttributes - Positionsnummer_Text: U100
 | H2 Ebene +1 | WI-HW 60 | 1163Wa 0813786484 | yes | Codetext | m² | Zimmer- und Holzbauarbeiten | Wand | Innenwand 1-Schalig | WI-HW 60 | 0 | A | 3.75 | 1163HWa0812438083 | NEW | no | no | 0 | 0 | no | 52 | no | Codetext | AllplanAttributes - ash W_laufende Nr. Statik: 3 (W 3.0); Positionsnummer_Text: U100
 | H2 Ebene +1 | WI-LB | 1163Wa 0813733900 | yes | Codetext | m² | Trockenbauarbeiten | Wand | Innenwand 1-Schalig | WI-LB | 0 | A | 3.75 | 1163HWa0813733891 | NEW | no | no | 0 | 0 | no | 47 | no | Codetext | AllplanAttributes - ash_W_Trockenbau_Qualitäten: 6; Sicherheitsklasse: -; Positionsnummer_Text: U100
 | H2 Ebene +1 | WI-HW 60 | 1163Wa 0813784175 | yes | Codetext | m² | Zimmer- und Holzbauarbeiten | Wand | Innenwand 1-Schalig | WI-HW 60 | 0 | A | 3.75 | 1163HWa0813733891 | NEW | no | no | 0 | 0 | no | 47 | no | Codetext | AllplanAttributes - Sicherheitsklasse: -; ash W_laufende Nr. Statik: 3 (W 3.0); Positionsnummer_Text: U100
 | H2 Ebene +1 | WI-LB | 1163Wa 0812447147 | yes | Codetext | m² | Trockenbauarbeiten | Wand | Innenwand 1-Schalig | WI-LB | 0 | A | 3.75 | 1163HWa0812430468 | NEW | no | no | 0 | 0 | no | 52 | no | Codetext | AllplanAttributes - ash_W_Trockenbau_Qualitäten: 8; Sicherheitsklasse: -; Positionsnummer_Text: U100
 | H2 Ebene +1 | Installationsraum | 1163Wa 0813783619 | yes | Codetext | m² | Trockenbauarbeiten | Wand | Innenwand 1-Schalig | Installationsraum | 0 | A | 3.75 | 1163HWa0812430468 | NEW | no | no | 0 | 0 | no | 52 | no | Codetext | AllplanAttributes - Positionsnummer_Text: U100
 | H2 Ebene +1 | WI-HW 60 | 1163Wa 0813783620 | yes | Codetext | m² | Zimmer- und Holzbauarbeiten | Wand | Innenwand 1-Schalig | WI-HW 60 | 0 | A | 3.75 | 1163HWa0812430468 | NEW | no | no | 0 | 0 | no | 52 | no | Codetext | AllplanAttributes - ash W_laufende Nr. Statik: 3 (W 3.0); Positionsnummer_Text: U100
 | H2 Ebene +1 | WI-LB | 1163Wa 0814196450 | yes | Codetext | m² | Trockenbauarbeiten | Wand | Innenwand 1-Schalig | WI-LB | 0 | A | 3.75 | 1163HWa0812428827 | NEW | no | no | 0 | 0 | no | 47 | no | Codetext | AllplanAttributes - ash_W_Trockenbau_Qualitäten: 8; Sicherheitsklasse: -; Positionsnummer_Text: U100
 | H2 Ebene +1 | Installationsraum | 1163Wa 0814196453 | yes | Codetext | m² | Trockenbauarbeiten | Wand | Innenwand 1-Schalig | Installationsraum | 0 | A | 3.75 | 1163HWa0812428827 | NEW | no | no | 0 | 0 | no | 0 | no | Codetext | AllplanAttributes - Sicherheitsklasse: -; Positionsnummer_Text: U100
 | H2 Ebene +1 | WI-HW 60 | 1163Wa 0814196452 | yes | Codetext | m² | Zimmer- und Holzbauarbeiten | Wand | Innenwand 1-Schalig | WI-HW 60 | 0 | A | 3.75 | 1163HWa0812428827 | NEW | no | no | 0 | 0 | no | 47 | no | Codetext | AllplanAttributes - Sicherheitsklasse: -; ash W_laufende Nr. Statik: 3 (W 3.0); Positionsnummer_Text: U100
 | H2 Ebene +1 | WI-LB | 1163Wa 0812754841 | yes | Codetext | m² | Trockenbauarbeiten | Wand | Innenwand 1-Schalig | WI-LB | 0 | A | 3.75 | 1163HWa0812754839 | NEW | no | no | 0 | 0 | no | 47 | no | Codetext | AllplanAttributes - ash_W_Trockenbau_Qualitäten: 8; Sicherheitsklasse: -; Positionsnummer_Text: U100
 | H2 Ebene +1 | Installationsraum | 1163Wa 0813782475 | yes | Codetext | m² | Trockenbauarbeiten | Wand | Innenwand 1-Schalig | Installationsraum | 0 | A | 3.75 | 1163HWa0812754839 | NEW | no | no | 0 | 0 | no | 0 | no | Codetext | AllplanAttributes - Sicherheitsklasse: -; Positionsnummer_Text: U100
 | H2 Ebene +1 | WI-HW 60 | 1163Wa 0814104273 | yes | Codetext | m² | Zimmer- und Holzbauarbeiten | Wand | Innenwand 1-Schalig | WI-HW 60 | 0 | A | 3.75 | 1163HWa0812754839 | NEW | no | no | 0 | 0 | no | 47 | no | Codetext | AllplanAttributes - Sicherheitsklasse: -; ash W_laufende Nr. Statik: 3 (W 3.0); Positionsnummer_Text: U100
 | H2 Ebene +1 | WI-LB | 1163Wa 0814198458 | yes | Codetext | m² | Trockenbauarbeiten | Wand | Innenwand 1-Schalig | WI-LB | 0 | A | 3.75 | 1163HWa0812428820 | NEW | no | no | 0 | 0 | no | 52 | no | Codetext | AllplanAttributes - ash_W_Trockenbau_Qualitäten: 8; Sicherheitsklasse: -; Positionsnummer_Text: U100
 | H2 Ebene +1 | Installationsraum | 1163Wa 0814198457 | yes | Codetext | m² | Trockenbauarbeiten | Wand | Innenwand 1-Schalig | Installationsraum | 0 | A | 3.75 | 1163HWa0812428820 | NEW | no | no | 0 | 0 | no | 0 | no | Codetext | AllplanAttributes - Sicherheitsklasse: -; Positionsnummer_Text: U100
 | H2 Ebene +1 | WI-HW 60 | 1163Wa 0814198460 | yes | Codetext | m² | Zimmer- und Holzbauarbeiten | Wand | Innenwand 1-Schalig | WI-HW 60 | 0 | A | 3.75 | 1163HWa0812428820 | NEW | no | no | 0 | 0 | no | 52 | no | Codetext | AllplanAttributes - Sicherheitsklasse: -; ash W_laufende Nr. Statik: 3 (W 3.0); Positionsnummer_Text: U100
 | H2 Ebene +1 | WI-LB | 1163Wa 0812439854 | yes | Codetext | m² | Trockenbauarbeiten | Wand | Innenwand 1-Schalig | WI-LB | 0 | A | 3.75 | 1163HWa0812438661 | NEW | no | no | 0 | 0 | no | 47 | no | Codetext | AllplanAttributes - ash_W_Trockenbau_Qualitäten: 8; Sicherheitsklasse: -; Positionsnummer_Text: U100
 | H2 Ebene +1 | Installationsraum | 1163Wa 0813788791 | yes | Codetext | m² | Trockenbauarbeiten | Wand | Innenwand 1-Schalig | Installationsraum | 0 | A | 3.75 | 1163HWa0812438661 | NEW | no | no | 0 | 0 | no | 0 | no | Codetext | AllplanAttributes - Sicherheitsklasse: -; Positionsnummer_Text: U100
 | H2 Ebene +1 | WI-HW 60 | 1163Wa 0814103096 | yes | Codetext | m² | Zimmer- und Holzbauarbeiten | Wand | Innenwand 1-Schalig | WI-HW 60 | 0 | A | 3.75 | 1163HWa0812438661 | NEW | no | no | 0 | 0 | no | 47 | no | Codetext | AllplanAttributes - Sicherheitsklasse: -; ash W_laufende Nr. Statik: 3 (W 3.0); Positionsnummer_Text: U100
 | H2 Ebene +1 | WI-LB | 1163Wa 0814183060 | yes | Codetext | m² | Trockenbauarbeiten | Wand | Innenwand 1-Schalig | WI-LB | 0 | A | 3.75 | 1163HWa0812492424 | NEW | no | no | REI 30-A1 - D,s2-d0 +A1 | 0 | no | 47 | no | Codetext | AllplanAttributes - ash_W_Trockenbau_Qualitäten: 8; Sicherheitsklasse: -; Positionsnummer_Text: U100
 | H2 Ebene +1 | Installationsraum | 1163Wa 0814183063 | yes | Codetext | m² | Trockenbauarbeiten | Wand | Innenwand 1-Schalig | Installationsraum | 0 | A | 3.75 | 1163HWa0812492424 | NEW | no | no | 0 | 0 | no | 47 | no | Codetext | AllplanAttributes - Sicherheitsklasse: -; Positionsnummer_Text: U100
 | H2 Ebene +1 | WI-HW 60 | 1163Wa 0814183059 | yes | Codetext | m² | Zimmer- und Holzbauarbeiten | Wand | Innenwand 1-Schalig | WI-HW 60 | 0 | A | 3.75 | 1163HWa0812492424 | NEW | no | no | REI 30-A1 - D,s2-d0 +A1 | 0 | no | 47 | no | Codetext | AllplanAttributes - Sicherheitsklasse: -; ash W_laufende Nr. Statik: 3 (W 3.0); Positionsnummer_Text: U100
 | H2 Ebene +1 | WI-LB | 1163Wa 0814290052 | yes | Codetext | m² | Trockenbauarbeiten | Wand | Innenwand 1-Schalig | WI-LB | 0 | A | 3.75 | 1163HWa0812492087 | NEW | no | no | REI 60-A1 - D,s2-d0 /A1 | 0 | no | 47 | no | Codetext | AllplanAttributes - ash_W_Trockenbau_Qualitäten: 6; Positionsnummer_Text: U100
 | H2 Ebene +1 | WI-HW 60 | 1163Wa 0814290055 | yes | Codetext | m² | Zimmer- und Holzbauarbeiten | Wand | Innenwand 1-Schalig | WI-HW 60 | 0 | A | 3.75 | 1163HWa0812492087 | NEW | yes | no | REI 60-A1 - D,s2-d0 +A1 | 0 | no | 47 | no | Codetext | AllplanAttributes - ash W_laufende Nr. Statik: 3 (W 3.0); Positionsnummer_Text: U100
 | H2 Ebene +1 | WI-LB | 1163Wa 0812492978 | yes | Codetext | m² | Trockenbauarbeiten | Wand | Innenwand 1-Schalig | WI-LB | 0 | A | 3.75 | 1163HWa0812492424 | NEW | no | no | REI 30-A1 - D,s2-d0 +A1 | 0 | no | 47 | no | Codetext | AllplanAttributes - ash_W_Trockenbau_Qualitäten: 8; Sicherheitsklasse: -; Positionsnummer_Text: U100
 | H2 Ebene +1 | Installationsraum | 1163Wa 0813789687 | yes | Codetext | m² | Trockenbauarbeiten | Wand | Innenwand 1-Schalig | Installationsraum | 0 | A | 3.75 | 1163HWa0812492424 | NEW | no | no | 0 | 0 | no | 47 | no | Codetext | AllplanAttributes - Sicherheitsklasse: -; Positionsnummer_Text: U100
 | H2 Ebene +1 | WI-HW 60 | 1163Wa 0813789688 | yes | Codetext | m² | Zimmer- und Holzbauarbeiten | Wand | Innenwand 1-Schalig | WI-HW 60 | 0 | A | 3.75 | 1163HWa0812492424 | NEW | no | no | REI 30-A1 - D,s2-d0 +A1 | 0 | no | 47 | no | Codetext | AllplanAttributes - Sicherheitsklasse: -; ash W_laufende Nr. Statik: 3 (W 3.0); Positionsnummer_Text: U100
 | H2 Ebene +1 | WI-LB | 1163Wa 0814245299 | yes | Codetext | m² | Trockenbauarbeiten | Wand | Innenwand 1-Schalig | WI-LB | 0 | A | 3.75 | 1163HWa0812425615 | NEW |  | no | 0 | 0 | no | 47 | no | Codetext | AllplanAttributes - ash_W_Trockenbau_Qualitäten: 6; Sicherheitsklasse: -; Positionsnummer_Text: U100
 | H2 Ebene +1 | WI-HW 60 | 1163Wa 0814245302 | yes | Codetext | m² | Zimmer- und Holzbauarbeiten | Wand | Innenwand 1-Schalig | WI-HW 60 | 0 | A | 3.75 | 1163HWa0812425615 | NEW |  | no | 0 | 0 | no | 47 | no | Codetext | AllplanAttributes - Sicherheitsklasse: -; ash W_laufende Nr. Statik: 3 (W 3.0); Positionsnummer_Text: U100
 | H2 Ebene +1 | WI-LB | 1163Wa 0814267660 | yes | Codetext | m² | Trockenbauarbeiten | Wand | Innenwand 1-Schalig | WI-LB | 0 | A | 3.75 | 1163HWa0812435322 | NEW |  | no | 0 | 0 | no | 47 | no | Codetext | AllplanAttributes - ash_W_Trockenbau_Qualitäten: 6; Sicherheitsklasse: -; Positionsnummer_Text: U100
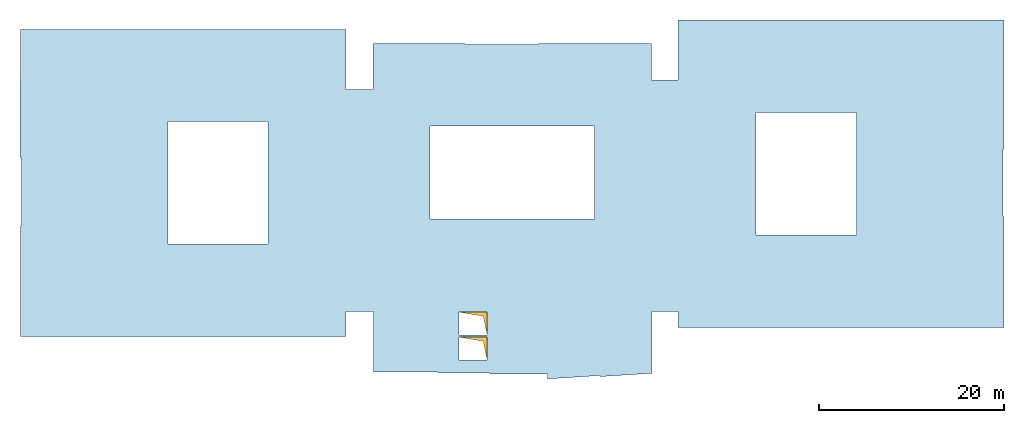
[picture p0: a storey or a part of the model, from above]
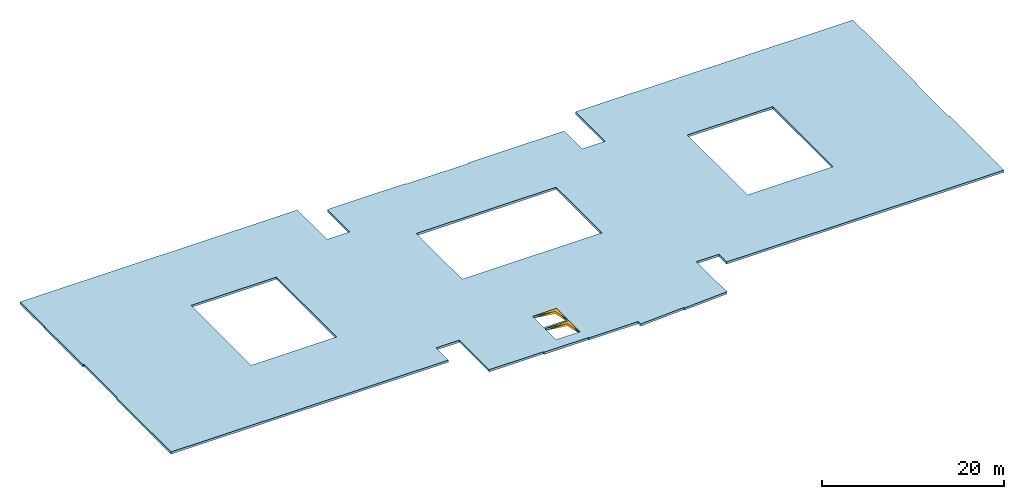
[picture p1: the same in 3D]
Properties of the parts of a building model (IFC4), part 64 of 80

# IfcWall (6826)
Name | In | Material | Allright_Bauteil_ID | 2D Interaktion | Codetext | Abrechnungsart | Gewerk | Objektname | Bezeichnung | AllplanAttributes, Material | Typ = SurfaceSpreadOfFlame | Brandschutzklasse | OKFF | P_ID | Status | LoadBearing | IsExternal | FireRating | ThermalTransmittance (W/K/m2) | Combustible | AcousticRating | Compartmentation | Reference
 | H2 Ebene +1 | WI-HW 60 | 1163Wa 0814267658 | yes | Codetext | m² | Zimmer- und Holzbauarbeiten | Wand | Innenwand 1-Schalig | WI-HW 60 | 0 | A | 3.75 | 1163HWa0812435322 | NEW |  | no | 0 | 0 | no | 47 | no | Codetext | AllplanAttributes - Sicherheitsklasse: -; ash W_laufende Nr. Statik: 3 (W 3.0); Positionsnummer_Text: U100
 | H2 Ebene +1 | WI-LB | 1163Wa 0814179184 | yes | Codetext | m² | Trockenbauarbeiten | Wand | Innenwand 1-Schalig | WI-LB | 0 | A | 3.75 | 1163HWa0812492424 | NEW | no | no | REI 30-A1 - D,s2-d0 +A1 | 0 | no | 47 | no | Codetext | AllplanAttributes - ash_W_Trockenbau_Qualitäten: 8; Sicherheitsklasse: -; Positionsnummer_Text: U100
 | H2 Ebene +1 | Installationsraum | 1163Wa 0814179188 | yes | Codetext | m² | Trockenbauarbeiten | Wand | Innenwand 1-Schalig | Installationsraum | 0 | A | 3.75 | 1163HWa0812492424 | NEW | no | no | 0 | 0 | no | 47 | no | Codetext | AllplanAttributes - Sicherheitsklasse: -; Positionsnummer_Text: U100
 | H2 Ebene +1 | WI-HW 60 | 1163Wa 0814179187 | yes | Codetext | m² | Zimmer- und Holzbauarbeiten | Wand | Innenwand 1-Schalig | WI-HW 60 | 0 | A | 3.75 | 1163HWa0812492424 | NEW | no | no | REI 30-A1 - D,s2-d0 +A1 | 0 | no | 47 | no | Codetext | AllplanAttributes - Sicherheitsklasse: -; ash W_laufende Nr. Statik: 3 (W 3.0); Positionsnummer_Text: U100
 | H2 Ebene +1 | WI-LB | 1163Wa 0813749148 | yes | Codetext | m² | Trockenbauarbeiten | Wand | Innenwand 1-Schalig | WI-LB | 0 | A | 3.75 | 1163HWa0813749139 | NEW | no | no | 0 | 0 | no | 47 | no | Codetext | AllplanAttributes - ash_W_Trockenbau_Qualitäten: 6; Sicherheitsklasse: -; Positionsnummer_Text: U100
 | H2 Ebene +1 | WI-HW 60 | 1163Wa 0813786835 | yes | Codetext | m² | Zimmer- und Holzbauarbeiten | Wand | Innenwand 1-Schalig | WI-HW 60 | 0 | A | 3.75 | 1163HWa0813749139 | NEW | no | no | 0 | 0 | no | 47 | no | Codetext | AllplanAttributes - Sicherheitsklasse: -; ash W_laufende Nr. Statik: 3 (W 3.0); Positionsnummer_Text: U100
 | H2 Ebene +1 | WI-HW 60 | 1163Wa 0814189225 | yes | Codetext | m² | Zimmer- und Holzbauarbeiten | Wand | Innenwand 1-Schalig | WI-HW 60 | 0 | A | 3.75 | 1163HWa0812430556 | NEW | yes | no | REI 60-A1 - D,s2-d0 +A1 | 0 | no | 52 | no | Codetext | AllplanAttributes - ash W_laufende Nr. Statik: 3 (W 3.0); Positionsnummer_Text: U100
 | H2 Ebene +1 | Installationsraum | 1163Wa 0814189223 | yes | Codetext | m² | Trockenbauarbeiten | Wand | Innenwand 1-Schalig | Installationsraum | 0 | A | 3.75 | 1163HWa0812430556 | NEW | no | no | 0 | 0 | no | 52 | no | Codetext | AllplanAttributes - Positionsnummer_Text: U100
 | H2 Ebene +1 | WI-LB | 1163Wa 0814189224 | yes | Codetext | m² | Trockenbauarbeiten | Wand | Innenwand 1-Schalig | WI-LB | 0 | A | 3.75 | 1163HWa0812430556 | NEW | no | no | REI 60-A1 - D,s2-d0 /A1 | 0 | no | 52 | no | Codetext | AllplanAttributes - ash_W_Trockenbau_Qualitäten: 6; Positionsnummer_Text: U100
 | H2 Ebene +1 | WI-HW 60 | 1163Wa 0813879290 | yes | Codetext | m² | Zimmer- und Holzbauarbeiten | Wand | Innenwand 1-Schalig | WI-HW 60 | 0 | A | 3.75 | 1163HWa0813879184 | NEW | yes | no | REI 60-A1 - D,s2-d0 +A1 | 0 | no | 47 | no | Codetext | AllplanAttributes - ash W_laufende Nr. Statik: 3 (W 3.0); Positionsnummer_Text: U100
 | H2 Ebene +1 | WI-LB | 1163Wa 0813879289 | yes | Codetext | m² | Trockenbauarbeiten | Wand | Innenwand 1-Schalig | WI-LB | 0 | A | 3.75 | 1163HWa0813879184 | NEW | no | no | REI 60-A1 - D,s2-d0 /A1 | 0 | no | 47 | no | Codetext | AllplanAttributes - ash_W_Trockenbau_Qualitäten: 6; Positionsnummer_Text: U100
 | H2 Ebene +1 | WI-LB | 1163Wa 0814292024 | yes | Codetext | m² | Trockenbauarbeiten | Wand | Innenwand 1-Schalig | WI-LB | 0 | A | 3.75 | 1163HWa0812438500 | NEW | no | no | REI 60-A1 - D,s2-d0 /A1 | 0 | no | 52 | no | Codetext | AllplanAttributes - ash_W_Trockenbau_Qualitäten: 6; Positionsnummer_Text: U100
 | H2 Ebene +1 | WI-HW 60 | 1163Wa 0814292023 | yes | Codetext | m² | Zimmer- und Holzbauarbeiten | Wand | Innenwand 1-Schalig | WI-HW 60 | 0 | A | 3.75 | 1163HWa0812438500 | NEW | yes | no | REI 60-A1 - D,s2-d0 +A1 | 0 | no | 52 | no | Codetext | AllplanAttributes - ash W_laufende Nr. Statik: 3 (W 3.0); Positionsnummer_Text: U100
 | H2 Ebene +1 | WI-LB | 1163Wa 0812474333 | yes | Codetext | m² | Trockenbauarbeiten | Wand | Innenwand 1-Schalig | WI-LB | 0 | A | 3.75 | 1163HWa0812474331 | NEW | no | no | REI 60-A1 - D,s2-d0 /A1 | 0 | no | 52 | no | Codetext | AllplanAttributes - ash_W_Trockenbau_Qualitäten: 6; Positionsnummer_Text: U100
 | H2 Ebene +1 | WI-HW 60 | 1163Wa 0813782537 | yes | Codetext | m² | Zimmer- und Holzbauarbeiten | Wand | Innenwand 1-Schalig | WI-HW 60 | 0 | A | 3.75 | 1163HWa0812474331 | NEW | yes | no | REI 60-A1 - D,s2-d0 +A1 | 0 | no | 52 | no | Codetext | AllplanAttributes - ash W_laufende Nr. Statik: 3 (W 3.0); Positionsnummer_Text: U100
 | H2 Ebene +1 | WI-STB | 1163Wa 0812437398 | yes | Codetext | m² | Zimmer- und Holzbauarbeiten | Wand | Außenwand 1-Schalig | WI-STB | 0 | A | 3.75 | 1163HWa0812429065 | NEW | yes | no | REI 60-A1 - D,s2-d0 /A1 | 0 | no | 52 | no | Codetext | AllplanAttributes - Positionsnummer_Text: U100
 | H2 Ebene +1 | WI-LB | 1163Wa 0812447076 | yes | Codetext | m² | Trockenbauarbeiten | Wand | Innenwand 1-Schalig | WI-LB | 0 | A | 3.75 | 1163HWa0812434677 | NEW | no | no | 0 | 0 | no | 52 | no | Codetext | AllplanAttributes - ash_W_Trockenbau_Qualitäten: 6; Sicherheitsklasse: -; Positionsnummer_Text: U100
 | H2 Ebene +1 | WI-HW 60 | 1163Wa 0813784806 | yes | Codetext | m² | Zimmer- und Holzbauarbeiten | Wand | Innenwand 1-Schalig | WI-HW 60 | 0 | A | 3.75 | 1163HWa0812434677 | NEW | no | no | 0 | 0 | no | 52 | no | Codetext | AllplanAttributes - Sicherheitsklasse: -; ash W_laufende Nr. Statik: 3 (W 3.0); Positionsnummer_Text: U100
 | H2 Ebene +1 | WI-HW 60 | 1163Wa 0812437932 | yes |  | m² | Zimmer- und Holzbauarbeiten | Wand | Innenwand 1-Schalig | WI-HW 60 |  |  | 3.75 | 1163HWa0812434549 | NEW | yes | no | REI-M 60-D,s2,d0 + A1 |  |  | 52 | AllplanAttributes - ash W_laufende Nr. Statik: 7 (W 6.0-1); Positionsnummer_Text: U100
 | H2 Ebene +1 | WI-LB | 1163Wa 0812447085 | yes | Codetext | m² | Trockenbauarbeiten | Wand | Innenwand 1-Schalig | WI-LB | 0 | A | 3.75 | 1163HWa0812435648 | NEW |  | no | 0 | 0 | no | 52 | no | Codetext | AllplanAttributes - W_Deckenanschluss: Gleitender Deckenanschluss Fall 01; ash_W_Trockenbau_Qualitäten: 4; Positionsnummer_Text: U100
 | H2 Ebene +1 | WI-LB | 1163Wa 0812447102 | yes | Codetext | m² | Trockenbauarbeiten | Wand | Innenwand 1-Schalig | WI-LB | 0 | A | 3.75 | 1163HWa0812434684 | NEW | no | no | 0 | 0 | no | 52 | no | Codetext | AllplanAttributes - ash_W_Trockenbau_Qualitäten: 6; Sicherheitsklasse: -; Positionsnummer_Text: U100
 | H2 Ebene +1 | WI-HW 60 | 1163Wa 0813785740 | yes | Codetext | m² | Zimmer- und Holzbauarbeiten | Wand | Innenwand 1-Schalig | WI-HW 60 | 0 | A | 3.75 | 1163HWa0812434684 | NEW | no | no | 0 | 0 | no | 52 | no | Codetext | AllplanAttributes - Sicherheitsklasse: -; ash W_laufende Nr. Statik: 3 (W 3.0); Positionsnummer_Text: U100
 | H2 Ebene +1 | WI-STB | 1163Wa 0812447121 | yes | Codetext | m² | Zimmer- und Holzbauarbeiten | Wand | Außenwand 1-Schalig | WI-STB | 0 | A | 3.75 | 1163HWa0812438085 | NEW | yes | no | REI 60-A1 - D,s2-d0 /A1 | 0 | no | 52 | no | Codetext | AllplanAttributes - Ortscode_Geschoßbezeichnung: E01; Positionsnummer_Text: U100
 | H2 Ebene +1 | WI-STB | 1163Wa 0812542268 | yes | Codetext | m² | Zimmer- und Holzbauarbeiten | Wand | Außenwand 1-Schalig | WI-STB | 0 | A | 3.75 | 1163HWa0812542249 | NEW | yes | no | REI 60-A1 - D,s2-d0 /A1 | 0 | no | 47 | no | Codetext | AllplanAttributes - Positionsnummer_Text: U100
 | H2 Ebene +1 | WI-LB | 1163Wa 0812542270 | yes | Codetext | m² | Trockenbauarbeiten | Wand | Außenwand 1-Schalig | WI-LB | 0 | A | 3.75 | 1163HWa0812542253 | NEW | no | no | REI 60-A1 - D,s2-d0 /A1 | 0 | no |  | no | Codetext | AllplanAttributes - Ortscode_Geschoßbezeichnung: E01; ash_W_Trockenbau_Qualitäten: 9; Positionsnummer_Text: U100
 | H2 Ebene +1 | WI-STB | 1163Wa 0812842005 | yes | Codetext | m² | Zimmer- und Holzbauarbeiten | Wand | Außenwand 1-Schalig | WI-STB | 0 | A | 3.75 | 1163HWa0812542253 | NEW | yes | no | REI 60-A1 - D,s2-d0 /A1 | 0 | no | 47 | no | Codetext | AllplanAttributes - Ortscode_Geschoßbezeichnung: E01; Positionsnummer_Text: U100
 | H2 Ebene +1 | WI-STB | 1163Wa 0812542172 | yes | Codetext | m² | Zimmer- und Holzbauarbeiten | Wand | Außenwand 1-Schalig | WI-STB | 0 | A | 3.75 | 1163HWa0812542148 | NEW | yes | no | REI 60-A1 - D,s2-d0 /A1 | 0 | no | 52 | no | Codetext | AllplanAttributes - Ortscode_Geschoßbezeichnung: E01; Positionsnummer_Text: U100
 | H2 Ebene +1 | WI-LB | 1163Wa 0812542159 | yes | Codetext | m² | Trockenbauarbeiten | Wand | Außenwand 1-Schalig | WI-LB | 0 | A | 3.75 | 1163HWa0812542154 | NEW | no | no | REI 60-A1 - D,s2-d0 /A1 | 0 | no |  | no | Codetext | AllplanAttributes - Ortscode_Geschoßbezeichnung: E01; ash_W_Trockenbau_Qualitäten: 9; Positionsnummer_Text: U100
 | H2 Ebene +1 | WI-STB | 1163Wa 0812842222 | yes | Codetext | m² | Betonarbeiten | Wand | Außenwand 1-Schalig | WI-STB | 0 | A | 3.75 | 1163HWa0812542154 | NEW | yes | no | REI 60-A1 - D,s2-d0 /A1 | 0 | no | 52 | no | Codetext | AllplanAttributes - Ortscode_Geschoßbezeichnung: E01; Positionsnummer_Text: U100
 | H2 Ebene +1 | WI-STB | 1163Wa 0812544540 | yes | Codetext | m² | Zimmer- und Holzbauarbeiten | Wand | Außenwand 1-Schalig | WI-STB | 0 | A | 3.75 | 1163HWa0812544534 | NEW | yes | no | REI 60-A1 - D,s2-d0 /A1 | 0 | no | 52 | no | Codetext | AllplanAttributes - Ortscode_Geschoßbezeichnung: E01; Positionsnummer_Text: U100
 | H2 Ebene +1 | WI-STB | 1163Wa 0812543041 | yes | Codetext | m² | Zimmer- und Holzbauarbeiten | Wand | Außenwand 1-Schalig | WI-STB | 0 | A | 3.75 | 1163HWa0812543033 | NEW | yes | no | REI 60-A1 - D,s2-d0 /A1 | 0 | no | 52 | no | Codetext | AllplanAttributes - Ortscode_Geschoßbezeichnung: E01; Positionsnummer_Text: U100
 | H2 Ebene +1 | WI-STB | 1163Wa 0812543037 | yes | Codetext | m² | Zimmer- und Holzbauarbeiten | Wand | Außenwand 1-Schalig | WI-STB | 0 | A | 3.75 | 1163HWa0812543032 | NEW | yes | no | REI 60-A1 - D,s2-d0 /A1 | 0 | no | 52 | no | Codetext | AllplanAttributes - Positionsnummer_Text: U100
 | H2 Ebene +1 | WI-STB | 1163Wa 0812447078 | yes | Codetext | m² | Zimmer- und Holzbauarbeiten | Wand | Außenwand 1-Schalig | WI-STB | 0 | A | 3.75 | 1163HWa0812434258 | NEW | yes | no | REI 60-A1 - D,s2-d0 /A1 | 0 | no | 52 | no | Codetext | AllplanAttributes - Positionsnummer_Text: U100
 | H2 Ebene +1 | WI-LB | 1163Wa 0812655007 | yes | Codetext | m² | Trockenbauarbeiten | Wand | Innenwand 1-Schalig | WI-LB | 0 | A | 3.75 | 1163HWa0812428697 | NEW | no | no | REI 60-A1 - D,s2-d0 /A1 | 0 | no | 0 | no | Codetext | AllplanAttributes - Positionsnummer_Text: U100
 | H2 Ebene +1 | WI-HW 60 | 1163Wa 0814408252 | yes | Codetext | m² | Zimmer- und Holzbauarbeiten | Wand | Innenwand 1-Schalig | WI-HW 60 | 0 | A | 3.75 | 1163HWa0812655006 | NEW | yes | no | REI 60-A1 - D,s2-d0 /A1 | 0 | no | 0 | no | Codetext | AllplanAttributes - ash W_laufende Nr. Statik: 3 (W 3.0); Positionsnummer_Text: U100
 | H2 Ebene +1 | WI-LB | 1163Wa 0812437386 | yes | Codetext | m² | Trockenbauarbeiten | Wand | Außenwand 1-Schalig | WI-LB | 0 | A | 3.75 | 1163HWa0812425635 | NEW | no | no | REI 60-A1 - D,s2-d0 /A1 | 0 | no | 0 | no | Codetext | AllplanAttributes - Ortscode_Geschoßbezeichnung: E01; W_Deckenanschluss: Gleitender Deckenanschluss Fall 01; ash_W_Trockenbau_Qualitäten: 1b; Positionsnummer_Text: U100
 | H2 Ebene +1 | WI-LB | 1163Wa 0812655411 | yes | Codetext | m² | Trockenbauarbeiten | Wand | Innenwand 1-Schalig | WI-LB | 0 | A | 3.75 | 1163HWa0812428688 | NEW | no | no | REI 60-A1 - D,s2-d0 /A1 | 0 | no | 0 | no | Codetext | AllplanAttributes - Positionsnummer_Text: U100
 | H2 Ebene +1 | WI-HW 60 | 1163Wa 0814411603 | yes | Codetext | m² | Zimmer- und Holzbauarbeiten | Wand | Innenwand 1-Schalig | WI-HW 60 | 0 | A | 3.75 | 1163HWa0812655408 | NEW | yes | no | REI 60-A1 - D,s2-d0 /A1 | 0 | no | 0 | no | Codetext | AllplanAttributes - ash W_laufende Nr. Statik: 3 (W 3.0); Positionsnummer_Text: U100
 | H2 Ebene +1 | WI-LW 60 | 1163Wa 0814461995 | yes |  | m² | Trockenbauarbeiten | Wand | Innenwand 1-Schalig | WI-LW 60 |  |  | 0 |  | NEW | no |  | 0 | AllplanAttributes - Sicherheitsklasse: -
 | H2 Ebene +1 | WI-LB | 1163Wa 0812446033 | yes | Codetext | m² | Trockenbauarbeiten | Wand | Innenwand 1-Schalig | WI-LB | 0 | A | 3.75 | 1163HWa0812445203 | NEW | no | no | 0 | 0 | no | 0 | no | Codetext | AllplanAttributes - W_Deckenanschluss: Gleitender Deckenanschluss Fall 03; ash_W_Trockenbau_Qualitäten: 1b; Positionsnummer_Text: U100
 | H2 Ebene +1 | WI-LB | 1163Wa 0812446106 | yes | Codetext | m² | Trockenbauarbeiten | Wand | Innenwand 1-Schalig | WI-LB | 0 | A | 3.75 | 1163HWa0812445207 | NEW | no | no | 0 | 0 | no | 0 | no | Codetext | AllplanAttributes - W_Deckenanschluss: Gleitender Deckenanschluss Fall 03; ash_W_Trockenbau_Qualitäten: 1b; Positionsnummer_Text: U100
 | H2 Ebene +1 | WI-LB | 1163Wa 0813666066 | yes | Codetext | m² | Trockenbauarbeiten | Wand | Innenwand 1-Schalig | WI-LB | 0 | A | 3.75 | 1163HWa0813666063 | NEW | no | no | 0 | 0 | no | 0 | no | Codetext | AllplanAttributes - W_Deckenanschluss: Gleitender Deckenanschluss Fall 03; ash_W_Trockenbau_Qualitäten: 1b; Positionsnummer_Text: U100
 | H2 Ebene +1 | WI-LB | 1163Wa 0812446102 | yes | Codetext | m² | Trockenbauarbeiten | Wand | Innenwand 1-Schalig | WI-LB | 0 | A | 3.75 | 1163HWa0812445205 | NEW | no | no | 0 | 0 | no | 0 | no | Codetext | AllplanAttributes - W_Deckenanschluss: Gleitender Deckenanschluss Fall 03; ash_W_Trockenbau_Qualitäten: 1b; Positionsnummer_Text: U100
 | H2 Ebene +1 | WI-LB | 1163Wa 0812446143 | yes | Codetext | m² | Trockenbauarbeiten | Wand | Innenwand 1-Schalig | WI-LB | 0 | A | 3.75 | 1163HWa0812445234 | NEW | no | no | 0 | 0 | no | 0 | no | Codetext | AllplanAttributes - W_Deckenanschluss: Gleitender Deckenanschluss Fall 03; ash_W_Trockenbau_Qualitäten: 1b; Positionsnummer_Text: U100
 | H2 Ebene +1 | WI-LB | 1163Wa 0812446714 | yes | Codetext | m² | Trockenbauarbeiten | Wand | Innenwand 1-Schalig | WI-LB | 0 | A | 3.75 | 1163HWa0812446711 | NEW | no | no | 0 | 0 | no | 0 | no | Codetext | AllplanAttributes - W_Deckenanschluss: Gleitender Deckenanschluss Fall 03; ash_W_Trockenbau_Qualitäten: 1b; Positionsnummer_Text: U100
 | H2 Ebene +1 | WI-LB | 1163Wa 0812437302 | yes | Codetext | m² | Trockenbauarbeiten | Wand | Innenwand 1-Schalig | WI-LB | 0 | A | 3.75 | 1163HWa0812435115 | NEW | no | no | 0 | 0 | no | 0 | no | Codetext | AllplanAttributes - W_Deckenanschluss: Gleitender Deckenanschluss Fall 03; ash_W_Trockenbau_Qualitäten: 1b; Positionsnummer_Text: U100
 | H2 Ebene +1 | WI-LB | 1163Wa 0812437300 | yes | Codetext | m² | Trockenbauarbeiten | Wand | Innenwand 1-Schalig | WI-LB | 0 | A | 3.75 | 1163HWa0812425517 | NEW | no | no | 0 | 0 | no | 0 | no | Codetext | AllplanAttributes - W_Deckenanschluss: Gleitender Deckenanschluss Fall 03; ash_W_Trockenbau_Qualitäten: 1b; Positionsnummer_Text: U100
 | H2 Ebene +1 | WI-LB | 1163Wa 0812437719 | yes | Codetext | m² | Trockenbauarbeiten | Wand | Innenwand 1-Schalig | WI-LB | 0 | A | 3.75 | 1163HWa0812425562 | NEW | no | no | 0 | 0 | no | 0 | no | Codetext | AllplanAttributes - W_Deckenanschluss: Gleitender Deckenanschluss Fall 03; ash_W_Trockenbau_Qualitäten: 1b; Positionsnummer_Text: U100
 | H2 Ebene +1 | WI-LB | 1163Wa 0814418469 | yes | Codetext | m² | Trockenbauarbeiten | Wand | Innenwand 1-Schalig | WI-LB | 0 | A | 3.75 | 1163HWa0813666029 | NEW | no | no | 0 | 0 | no | 0 | no | Codetext | AllplanAttributes - W_Deckenanschluss: Gleitender Deckenanschluss Fall 03; ash_W_Trockenbau_Qualitäten: 1b; Positionsnummer_Text: U100
 | H2 Ebene +1 | WI-LB | 1163Wa 0814418467 | yes | Codetext | m² | Trockenbauarbeiten | Wand | Innenwand 1-Schalig | WI-LB | 0 | A | 3.75 | 1163HWa0812425514 | NEW | no | no | 0 | 0 | no | 0 | no | Codetext | AllplanAttributes - W_Deckenanschluss: Gleitender Deckenanschluss Fall 03; ash_W_Trockenbau_Qualitäten: 1b; Positionsnummer_Text: U100
 | H2 Ebene +1 | WI-LB | 1163Wa 0812437679 | yes | Codetext | m² | Trockenbauarbeiten | Wand | Innenwand 1-Schalig | WI-LB | 0 | A | 3.75 | 1163HWa0812425542 | NEW | no | no | 0 | 0 | no | 0 | no | Codetext | AllplanAttributes - W_Deckenanschluss: Gleitender Deckenanschluss Fall 03; ash_W_Trockenbau_Qualitäten: 1b; Positionsnummer_Text: U100
 | H2 Ebene +1 | WI-LB | 1163Wa 0812438262 |  | Codetext | m² | Trockenbauarbeiten | Wand | Innenwand 1-Schalig | WI-LB | 0 | A | 3.75 | 1163HWa0812425516 | NEW |  | no | REI 30 | 0 | no | 47 | no | Codetext | AllplanAttributes - Ortscode_Geschoßbezeichnung: E01; W_Deckenanschluss: Gleitender Deckenanschluss Fall 03; ash_W_Trockenbau_Qualitäten: 1c; Positionsnummer_Text: U100
 | H2 Ebene +1 | WI-LB | 1163Wa 0812439306 |  | Codetext | m² | Trockenbauarbeiten | Wand | Innenwand 1-Schalig | WI-LB | 0 | A | 3.75 | 1163HWa0812425580 | NEW |  | no | REI 30 | 0 | no | 47 | no | Codetext | AllplanAttributes - Ortscode_Geschoßbezeichnung: E01; W_Deckenanschluss: Gleitender Deckenanschluss Fall 03; ash_W_Trockenbau_Qualitäten: 1c; Positionsnummer_Text: U100
 | H2 Ebene +1 | WI-GKF | 1163Wa 0812834501 | yes | Codetext | m² | Trockenbauarbeiten | Wand | "BS-Beplankung; 2-fach Gipsfaserplatten" | WI-GKF | 0 | A | 3.75 | 1163HWa0812834484 | NEW | no | no | EI 60-A1 - D,s2,d0 +A1 | 0 | no | 0 | no | Codetext | AllplanAttributes - Ortscode_Geschoßbezeichnung: E01; Positionsnummer_Text: U100
 | H2 Ebene +1 | WI-HW 60 | 1163Wa 0814477900 | yes |  | m² | Zimmer- und Holzbauarbeiten | Wand | Innenwand 1-Schalig | WI-HW 60 |  |  | 3.75 | 1163HWa0812430471 | NEW |  | no | REI-M 60-D,s2,d0 + A1 | AllplanAttributes - ash W_laufende Nr. Statik: 7 (W 6.0-1); Positionsnummer_Text: U100
 | H2 Ebene +1 | WI-HW 60 | 1163Wa 0812551342 | yes | Codetext | m² | Zimmer- und Holzbauarbeiten | Wand | Innenwand 1-Schalig | WI-HW 60 | 0 | A | 3.75 | 1163HWa0812551330 | NEW | yes | no | REI 30-A1 - D,s2-d0 +A1 | 0 | no | 0 | no | Codetext | AllplanAttributes - ash W_laufende Nr. Statik: 3 (W 3.0); Positionsnummer_Text: U100
 | H2 Ebene +1 | WI-HW 60 | 1163Wa 0812551373 | yes | Codetext | m² | Zimmer- und Holzbauarbeiten | Wand | Innenwand 1-Schalig | WI-HW 60 | 0 | A | 3.75 | 1163HWa0812551364 | NEW | yes | no | REI 30-A1 - D,s2-d0 +A1 | 0 | no | 0 | no | Codetext | AllplanAttributes - ash W_laufende Nr. Statik: 1 (W 1.0/ 1.1/ 1.2); Positionsnummer_Text: U100
 | H2 Ebene +1 | WI-GKF | 1163Wa 0812812472 | yes | Codetext | m² | Trockenbauarbeiten | Wand | "BS-Beplankung; 2-fach Gipsfaserplatten" | WI-GKF | 0 | A | 3.75 | 1163HWa0812812471 | NEW | no | no | EI 60-A1 - D,s2,d0 +A1 | 0 | no | 0 | no | Codetext | AllplanAttributes - Ortscode_Geschoßbezeichnung: E01; Positionsnummer_Text: U100
 | H2 Ebene +1 | WI-GKF | 1163Wa 0812812402 | yes | Codetext | m² | Trockenbauarbeiten | Wand | "BS-Beplankung; 2-fach Gipsfaserplatten" | WI-GKF | 0 | A | 3.75 | 1163HWa0812812401 | NEW | no | no | EI 60-A1 - D,s2,d0 +A1 | 0 | no | 0 | no | Codetext | AllplanAttributes - Ortscode_Geschoßbezeichnung: E01; Positionsnummer_Text: U100
 | H2 Ebene +1 | WI-GKF | 1163Wa 0812812421 | yes | Codetext | m² | Trockenbauarbeiten | Wand | "BS-Beplankung; 2-fach Gipsfaserplatten" | WI-GKF | 0 | A | 3.75 | 1163HWa0812812420 | NEW | no | no | EI 60-A1 - D,s2,d0 +A1 | 0 | no | 0 | no | Codetext | AllplanAttributes - Ortscode_Geschoßbezeichnung: E01; Positionsnummer_Text: U100
 | H2 Ebene +1 | WI-GKF | 1163Wa 0812812440 | yes | Codetext | m² | Trockenbauarbeiten | Wand | "BS-Beplankung; 2-fach Gipsfaserplatten" | WI-GKF | 0 | A | 3.75 | 1163HWa0812812439 | NEW | no | no | EI 60-A1 - D,s2,d0 +A1 | 0 | no | 0 | no | Codetext | AllplanAttributes - Ortscode_Geschoßbezeichnung: E01; Positionsnummer_Text: U100
 | H2 Ebene +1 | WI-GKF | 1163Wa 0812812388 | yes | Codetext | m² | Trockenbauarbeiten | Wand | "BS-Beplankung; 2-fach Gipsfaserplatten" | WI-GKF | 0 | A | 3.75 | 1163HWa0812812387 | NEW | no | no | EI 60-A1 - D,s2,d0 +A1 | 0 | no | 0 | no | Codetext | AllplanAttributes - Ortscode_Geschoßbezeichnung: E01; Positionsnummer_Text: U100
 | H2 Ebene +1 | WI-GKF | 1163Wa 0812812369 | yes | Codetext | m² | Trockenbauarbeiten | Wand | "BS-Beplankung; 2-fach Gipsfaserplatten" | WI-GKF | 0 | A | 3.75 | 1163HWa0812812368 | NEW | no | no | EI 60-A1 - D,s2,d0 +A1 | 0 | no | 0 | no | Codetext | AllplanAttributes - Ortscode_Geschoßbezeichnung: E01; Positionsnummer_Text: U100
 | H2 Ebene +1 | WI-GKF | 1163Wa 0812812428 | yes | Codetext | m² | Trockenbauarbeiten | Wand | "BS-Beplankung; 2-fach Gipsfaserplatten" | WI-GKF | 0 | A | 3.75 | 1163HWa0812812427 | NEW | no | no | EI 60-A1 - D,s2,d0 +A1 | 0 | no | 0 | no | Codetext | AllplanAttributes - Ortscode_Geschoßbezeichnung: E01; Positionsnummer_Text: U100
 | H2 Ebene +1 | WI-GKF | 1163Wa 0812812281 | yes | Codetext | m² | Trockenbauarbeiten | Wand | "BS-Beplankung; 2-fach Gipsfaserplatten" | WI-GKF | 0 | A | 3.75 | 1163HWa0812812280 | NEW | no | no | EI 60-A1 - D,s2,d0 +A1 | 0 | no | 0 | no | Codetext | AllplanAttributes - Ortscode_Geschoßbezeichnung: E01; Positionsnummer_Text: U100
 | H2 Ebene +1 | WI-GKF | 1163Wa 0812812293 | yes | Codetext | m² | Trockenbauarbeiten | Wand | "BS-Beplankung; 2-fach Gipsfaserplatten" | WI-GKF | 0 | A | 3.75 | 1163HWa0812812292 | NEW | no | no | EI 60-A1 - D,s2,d0 +A1 | 0 | no | 0 | no | Codetext | AllplanAttributes - Ortscode_Geschoßbezeichnung: E01; Positionsnummer_Text: U100
 | H2 Ebene +1 | WI-GKF | 1163Wa 0812811194 | yes | Codetext | m² | Trockenbauarbeiten | Wand | "BS-Beplankung; 2-fach Gipsfaserplatten" | WI-GKF | 0 | A | 3.75 | 1163HWa0812811193 | NEW | no | no | EI 60-A1 - D,s2,d0 +A1 | 0 | no | 0 | no | Codetext | AllplanAttributes - Ortscode_Geschoßbezeichnung: E01; Positionsnummer_Text: U100
 | H2 Ebene +1 | WI-GKF | 1163Wa 0812812307 | yes | Codetext | m² | Trockenbauarbeiten | Wand | "BS-Beplankung; 2-fach Gipsfaserplatten" | WI-GKF | 0 | A | 3.75 | 1163HWa0812812306 | NEW | no | no | EI 60-A1 - D,s2,d0 +A1 | 0 | no | 0 | no | Codetext | AllplanAttributes - Ortscode_Geschoßbezeichnung: E01; Positionsnummer_Text: U100
 | H2 Ebene +1 | WI-GKF | 1163Wa 0812834460 | yes | Codetext | m² | Trockenbauarbeiten | Wand | "BS-Beplankung; 2-fach Gipsfaserplatten" | WI-GKF | 0 | A | 3.75 | 1163HWa0812834455 | NEW | no | no | EI 60-A1 - D,s2,d0 +A1 | 0 | no | 0 | no | Codetext | AllplanAttributes - Ortscode_Geschoßbezeichnung: E01; Positionsnummer_Text: U100
 | H2 Ebene +1 | WI-GKF | 1163Wa 0813764798 | yes | Codetext | m² | Trockenbauarbeiten | Wand | "BS-Beplankung; 2-fach Gipsfaserplatten" | WI-GKF | 0 | A | 3.75 | 1163HWa0813764796 | NEW | no | no | EI 60-A1 - D,s2,d0 +A1 | 0 | no | 0 | no | Codetext | AllplanAttributes - Ortscode_Geschoßbezeichnung: E01; Positionsnummer_Text: U100
 | H2 Ebene +1 | WI-GKF | 1163Wa 0813764757 | yes | Codetext | m² | Trockenbauarbeiten | Wand | "BS-Beplankung; 2-fach Gipsfaserplatten" | WI-GKF | 0 | A | 3.75 | 1163HWa0813764755 | NEW | no | no | EI 60-A1 - D,s2,d0 +A1 | 0 | no | 0 | no | Codetext | AllplanAttributes - Ortscode_Geschoßbezeichnung: E01; Positionsnummer_Text: U100
 | H2 Ebene +1 | WI-GKF | 1163Wa 0813764808 | yes | Codetext | m² | Trockenbauarbeiten | Wand | "BS-Beplankung; 2-fach Gipsfaserplatten" | WI-GKF | 0 | A | 3.75 | 1163HWa0813764806 | NEW | no | no | EI 60-A1 - D,s2,d0 +A1 | 0 | no | 0 | no | Codetext | AllplanAttributes - Ortscode_Geschoßbezeichnung: E01; Positionsnummer_Text: U100
 | H2 Ebene +1 | WI-GKF | 1163Wa 0813764689 | yes | Codetext | m² | Trockenbauarbeiten | Wand | "BS-Beplankung; 2-fach Gipsfaserplatten" | WI-GKF | 0 | A | 3.75 | 1163HWa0813764687 | NEW | no | no | EI 60-A1 - D,s2,d0 +A1 | 0 | no | 0 | no | Codetext | AllplanAttributes - Ortscode_Geschoßbezeichnung: E01; Positionsnummer_Text: U100
 | H2 Ebene +1 | WI-GKF | 1163Wa 0812834503 | yes | Codetext | m² | Trockenbauarbeiten | Wand | "BS-Beplankung; 2-fach Gipsfaserplatten" | WI-GKF | 0 | A | 3.75 | 1163HWa0812834480 | NEW | no | no | EI 60-A1 - D,s2,d0 +A1 | 0 | no | 0 | no | Codetext | AllplanAttributes - Ortscode_Geschoßbezeichnung: E01; Positionsnummer_Text: U100
 | H2 Ebene +1 | WI-GKF | 1163Wa 0812834474 | yes | Codetext | m² | Trockenbauarbeiten | Wand | "BS-Beplankung; 2-fach Gipsfaserplatten" | WI-GKF | 0 | A | 3.75 | 1163HWa0812834468 | NEW | no | no | EI 60-A1 - D,s2,d0 +A1 | 0 | no | 0 | no | Codetext | AllplanAttributes - Ortscode_Geschoßbezeichnung: E01; Positionsnummer_Text: U100
 | H2 Ebene +1 | WI-GKF | 1163Wa 0812834505 | yes | Codetext | m² | Trockenbauarbeiten | Wand | "BS-Beplankung; 2-fach Gipsfaserplatten" | WI-GKF | 0 | A | 3.75 | 1163HWa0812834479 | NEW | no | no | EI 60-A1 - D,s2,d0 +A1 | 0 | no | 0 | no | Codetext | AllplanAttributes - Ortscode_Geschoßbezeichnung: E01; Positionsnummer_Text: U100
 | H2 Ebene +1 | WI-GKF | 1163Wa 0813764939 | yes | Codetext | m² | Trockenbauarbeiten | Wand | "BS-Beplankung; 2-fach Gipsfaserplatten" | WI-GKF | 0 | A | 3.75 | 1163HWa0813764937 | NEW | no | no | EI 60-A1 - D,s2,d0 +A1 | 0 | no | 0 | no | Codetext | AllplanAttributes - Ortscode_Geschoßbezeichnung: E01; Positionsnummer_Text: U100
 | H2 Ebene +1 | WI-GKF | 1163Wa 0812834471 | yes | Codetext | m² | Trockenbauarbeiten | Wand | "BS-Beplankung; 2-fach Gipsfaserplatten" | WI-GKF | 0 | A | 3.75 | 1163HWa0812834466 | NEW | no | no | EI 60-A1 - D,s2,d0 +A1 | 0 | no | 0 | no | Codetext | AllplanAttributes - Ortscode_Geschoßbezeichnung: E01; Positionsnummer_Text: U100
 | H2 Ebene +1 | WI-LB | 1163Wa 0812439336 |  | Codetext | m² | Trockenbauarbeiten | Wand |  |  | 0 | A | 3.75 | 1163HWa0812425485 | NEW | no | no | 0 | 0 | no | 0 | no | Codetext | AllplanAttributes - Ortscode_Geschoßbezeichnung: E01; W_Deckenanschluss: Gleitender Deckenanschluss Fall 03; ash_W_Trockenbau_Qualitäten: 10a; Positionsnummer_Text: U100
 | H2 Ebene +1 | WI-LB | 1163Wa 0812439332 |  | Codetext | m² | Trockenbauarbeiten | Wand |  |  | 0 | A | 3.75 | 1163HWa0812425486 | NEW | no | no | 0 | 0 | no | 0 | no | Codetext | AllplanAttributes - Ortscode_Geschoßbezeichnung: E01; W_Deckenanschluss: Gleitender Deckenanschluss Fall 03; ash_W_Trockenbau_Qualitäten: 10a; Positionsnummer_Text: U100
 | H2 Ebene +1 | WI-LB | 1163Wa 0812439312 |  | Codetext | m² | Trockenbauarbeiten | Wand |  |  | 0 | A | 3.75 | 1163HWa0812425499 | NEW | no | no | 0 | 0 | no | 0 | no | Codetext | AllplanAttributes - Ortscode_Geschoßbezeichnung: E01; W_Deckenanschluss: Gleitender Deckenanschluss Fall 03; ash_W_Trockenbau_Qualitäten: 10a; Positionsnummer_Text: U100
 | H2 Ebene +1 | WI-LB | 1163Wa 0812439344 |  | Codetext | m² | Trockenbauarbeiten | Wand |  |  | 0 | A | 3.75 | 1163HWa0812425564 | NEW | no | no | 0 | 0 | no | 0 | no | Codetext | AllplanAttributes - Ortscode_Geschoßbezeichnung: E01; W_Deckenanschluss: Gleitender Deckenanschluss Fall 03; ash_W_Trockenbau_Qualitäten: 10a; Positionsnummer_Text: U100
 | H2 Ebene +1 | WI-LB | 1163Wa 0812439340 |  | Codetext | m² | Trockenbauarbeiten | Wand |  |  | 0 | A | 3.75 | 1163HWa0812425573 | NEW | no | no | 0 | 0 | no | 0 | no | Codetext | AllplanAttributes - Ortscode_Geschoßbezeichnung: E01; W_Deckenanschluss: Gleitender Deckenanschluss Fall 03; ash_W_Trockenbau_Qualitäten: 10a; Positionsnummer_Text: U100
 | H2 Ebene +1 | WI-LB | 1163Wa 0812439316 |  | Codetext | m² | Trockenbauarbeiten | Wand |  |  | 0 | A | 3.75 | 1163HWa0812427802 | NEW | no | no | 0 | 0 | no | 0 | no | Codetext | AllplanAttributes - Ortscode_Geschoßbezeichnung: E01; W_Deckenanschluss: Gleitender Deckenanschluss Fall 03; ash_W_Trockenbau_Qualitäten: 10a; Positionsnummer_Text: U100
 | H2 Ebene +1 | WI-LB | 1163Wa 0812437723 |  | Codetext | m² | Trockenbauarbeiten | Wand |  |  | 0 | A | 3.75 | 1163HWa0812425484 | NEW | no | no | 0 | 0 | no | 0 | no | Codetext | AllplanAttributes - Ortscode_Geschoßbezeichnung: E01; W_Deckenanschluss: Gleitender Deckenanschluss Fall 03; ash_W_Trockenbau_Qualitäten: 10a; Positionsnummer_Text: U100
 | H2 Ebene +1 | WI-LB | 1163Wa 0812437755 |  | Codetext | m² | Trockenbauarbeiten | Wand |  |  | 0 | A | 3.75 | 1163HWa0812425507 | NEW | no | no | 0 | 0 | no | 0 | no | Codetext | AllplanAttributes - Ortscode_Geschoßbezeichnung: E01; W_Deckenanschluss: Gleitender Deckenanschluss Fall 03; ash_W_Trockenbau_Qualitäten: 10a; Positionsnummer_Text: U100
 | H2 Ebene +1 | WI-LB | 1163Wa 0812437729 |  | Codetext | m² | Trockenbauarbeiten | Wand |  |  | 0 | A | 3.75 | 1163HWa0812425574 | NEW | no | no | 0 | 0 | no | 0 | no | Codetext | AllplanAttributes - Ortscode_Geschoßbezeichnung: E01; W_Deckenanschluss: Gleitender Deckenanschluss Fall 03; ash_W_Trockenbau_Qualitäten: 10a; Positionsnummer_Text: U100
 | H2 Ebene +1 | WI-LB | 1163Wa 0812437725 | yes | Codetext | m² | Trockenbauarbeiten | Wand | Innenwand 1-Schalig | WI-LB | 0 | A | 3.75 | 1163HWa0812425481 | NEW | no | no | 0 | 0 | no | 0 | no | Codetext | AllplanAttributes - W_Deckenanschluss: Gleitender Deckenanschluss Fall 03; ash_W_Trockenbau_Qualitäten: 1b; Positionsnummer_Text: U100
 | H2 Ebene +1 | WI-LB | 1163Wa 0812437727 | yes | Codetext | m² | Trockenbauarbeiten | Wand | Innenwand 1-Schalig | WI-LB | 0 | A | 3.75 | 1163HWa0812425582 | NEW | no | no | 0 | 0 | no | 0 | no | Codetext | AllplanAttributes - W_Deckenanschluss: Gleitender Deckenanschluss Fall 03; ash_W_Trockenbau_Qualitäten: 1b; Positionsnummer_Text: U100
 | H2 Ebene +1 | WI-LB | 1163Wa 0813666041 | yes | Codetext | m² | Trockenbauarbeiten | Wand | Innenwand 1-Schalig | WI-LB | 0 | A | 3.75 | 1163HWa0813666039 | NEW | no | no | 0 | 0 | no | 0 | no | Codetext | AllplanAttributes - W_Deckenanschluss: Gleitender Deckenanschluss Fall 03; ash_W_Trockenbau_Qualitäten: 1b; Positionsnummer_Text: U100
 | H2 Ebene +1 | WI-LB | 1163Wa 0812437681 | yes | Codetext | m² | Trockenbauarbeiten | Wand | Innenwand 1-Schalig | WI-LB | 0 | A | 3.75 | 1163HWa0812425512 | NEW | no | no | 0 | 0 | no | 0 | no | Codetext | AllplanAttributes - W_Deckenanschluss: Gleitender Deckenanschluss Fall 03; ash_W_Trockenbau_Qualitäten: 1b; Positionsnummer_Text: U100
 | H2 Ebene +1 | WI-LB | 1163Wa 0814418459 | yes | Codetext | m² | Trockenbauarbeiten | Wand | Innenwand 1-Schalig | WI-LB | 0 | A | 3.75 | 1163HWa0812425477 | NEW | no | no | 0 | 0 | no | 0 | no | Codetext | AllplanAttributes - W_Deckenanschluss: Gleitender Deckenanschluss Fall 03; ash_W_Trockenbau_Qualitäten: 1b; Positionsnummer_Text: U100
 | H2 Ebene +1 | WI-LB | 1163Wa 0812437922 | yes | Codetext | m² | Trockenbauarbeiten | Wand | Innenwand 1-Schalig | WI-LB | 0 | A | 3.75 | 1163HWa0812434542 | NEW | no | no | 0 | 0 | no |  | no | Codetext | AllplanAttributes - Ortscode_Geschoßbezeichnung: E01; W_Deckenanschluss: Gleitender Deckenanschluss Fall 01; ash_W_Trockenbau_Qualitäten: 4; Positionsnummer_Text: U100
 | H2 Ebene +1 | WI-LB | 1163Wa 0812437339 | yes | Codetext | m² | Trockenbauarbeiten | Wand | Innenwand 1-Schalig | WI-LB | 0 | A | 3.75 | 1163HWa0812434425 | NEW | no | no | 0 | 0 | no |  | no | Codetext | AllplanAttributes - Ortscode_Geschoßbezeichnung: E01; W_Deckenanschluss: Gleitender Deckenanschluss Fall 01; ash_W_Trockenbau_Qualitäten: 4; Positionsnummer_Text: U100
 | H2 Ebene +1 | WI-LB | 1163Wa 0812442543 | yes | Codetext | m² | Trockenbauarbeiten | Wand | Innenwand 1-Schalig | WI-LB | 0 | A | 3.75 | 1163HWa0812425642 | NEW | no | no | 0 | 0 | no | 47 | no | Codetext | AllplanAttributes - Ortscode_Geschoßbezeichnung: E01; W_Deckenanschluss: Gleitender Deckenanschluss Fall 01; ash_W_Trockenbau_Qualitäten: 1b; Positionsnummer_Text: U100
 | H2 Ebene +1 | WI-LB | 1163Wa 0812446743 |  | Codetext | m² | Trockenbauarbeiten | Wand |  |  | 0 | A | 3.75 | 1163HWa0812445891 | NEW | no | no | 0 | 0 | no | 0 | no | Codetext | AllplanAttributes - Ortscode_Geschoßbezeichnung: E01; W_Deckenanschluss: Gleitender Deckenanschluss Fall 03; ash_W_Trockenbau_Qualitäten: 10a; Positionsnummer_Text: U100
 | H2 Ebene +1 | WI-LB | 1163Wa 0814484058 | yes | Codetext | m² | Trockenbauarbeiten | Wand | Innenwand 1-Schalig | WI-LB | 0 | A | 3.75 | 1163HWa0812443364 | NEW | no | no | REI 30-A1 - D,s2-d0 +A1 | 0 | no | 47 | no | Codetext | AllplanAttributes - Ortscode_Geschoßbezeichnung: E01; W_Deckenanschluss: Gleitender Deckenanschluss Fall 01; ash_W_Trockenbau_Qualitäten: 1b; Positionsnummer_Text: U100
 | H2 Ebene +1 | WI-LB | 1163Wa 0812443007 |  | Codetext | m² | Trockenbauarbeiten | Wand | Innenwand 1-Schalig | WI-LB | 0 | A | 3.75 | 1163HWa0812442703 | NEW |  | no | REI 60-A1 - D,s2-d0 +A1 | 0 | no | 0 | no | Codetext | AllplanAttributes - Ortscode_Geschoßbezeichnung: E01; W_Deckenanschluss: Gleitender Deckenanschluss Fall 01; ash_W_Trockenbau_Qualitäten: 1b; Positionsnummer_Text: U100
 | H2 Ebene +1 | WI-LB | 1163Wa 0812496646 | yes | Codetext | m² | Trockenbauarbeiten | Wand | Innenwand 1-Schalig | WI-LB | 0 | A | 3.75 | 1163HWa0812496570 | NEW | no | no | REI 30-A1 - D,s2-d0 +A1 | 0 | no | 47 | no | Codetext | AllplanAttributes - Ortscode_Geschoßbezeichnung: E01; W_Deckenanschluss: Gleitender Deckenanschluss Fall 01; ash_W_Trockenbau_Qualitäten: 1b; Positionsnummer_Text: U100
 | H2 Ebene +1 | WI-LB | 1163Wa 0812437379 | yes | Codetext | m² | Trockenbauarbeiten | Wand | Innenwand 1-Schalig | WI-LB | 0 | A | 3.75 | 1163HWa0812428611 | NEW | no | no | 0 | 0 | no | 0 | no | Codetext | AllplanAttributes - Ortscode_Geschoßbezeichnung: E01; W_Deckenanschluss: Gleitender Deckenanschluss Fall 01; ash_W_Trockenbau_Qualitäten: 1b; Positionsnummer_Text: U100
 | H2 Ebene +1 | WI-LB | 1163Wa 0814484913 | yes | Codetext | m² | Trockenbauarbeiten | Wand | Innenwand 1-Schalig | WI-LB | 0 | A | 3.75 | 1163HWa0812430876 | NEW |  | no | REI 60-A1 - D,s2-d0 +A1 | 0 | no | 0 | no | Codetext | AllplanAttributes - Ortscode_Geschoßbezeichnung: E01; W_Deckenanschluss: Gleitender Deckenanschluss Fall 01; ash_W_Trockenbau_Qualitäten: 1b; Positionsnummer_Text: U100
 | H2 Ebene +1 | WI-LB | 1163Wa 0812443219 | yes | Codetext | m² | Trockenbauarbeiten | Wand | Innenwand 1-Schalig | WI-LB | 0 | A | 3.75 | 1163HWa0812425627 | NEW |  | no | 0 | 0 | no | 47 | no | Codetext | AllplanAttributes - Ortscode_Geschoßbezeichnung: E01; W_Deckenanschluss: Gleitender Deckenanschluss Fall 01; ash_W_Trockenbau_Qualitäten: 1b; Positionsnummer_Text: U100
 | H2 Ebene +1 | WI-STB | 1163Wa 0814409604 | yes |  | m² | Zimmer- und Holzbauarbeiten | Wand | Innenwand 1-Schalig | WI-STB |  |  | 0 |  | NEW |  |  | 0 |  |  | 0 | AllplanAttributes - Sicherheitsklasse: -
 | H2 Ebene +1 | WI-STB | 1163Wa 0814409605 | yes |  | m² | Zimmer- und Holzbauarbeiten | Wand | Innenwand 1-Schalig | WI-STB |  |  | 0 |  | NEW |  |  | 0 |  |  | 0 | AllplanAttributes - Sicherheitsklasse: -
 | H2 Ebene +1 | WI-LB | 1163Wa 0814409606 | yes |  | m² | Trockenbauarbeiten | Wand | Innenwand 1-Schalig | WI-LB |  |  | 0 |  | NEW |  |  | 0 |  |  | 0 | AllplanAttributes - ash_W_Trockenbau_Qualitäten: 9; Sicherheitsklasse: -
 | H2 Ebene +1 | WI-STB | 1163Wa 0814486303 | yes |  | m² | Zimmer- und Holzbauarbeiten | Wand | Innenwand 1-Schalig | WI-STB |  |  | 0 |  | NEW |  |  | 0 |  |  | 0 | AllplanAttributes - Sicherheitsklasse: -
 | H2 Ebene +1 | WI-STB | 1163Wa 0814486304 | yes |  | m² | Zimmer- und Holzbauarbeiten | Wand | Innenwand 1-Schalig | WI-STB |  |  | 0 |  | NEW |  |  | 0 |  |  | 0 | AllplanAttributes - Sicherheitsklasse: -
 | H2 Ebene +1 | WI-LB | 1163Wa 0814486305 | yes |  | m² | Trockenbauarbeiten | Wand | Innenwand 1-Schalig | WI-LB |  |  | 0 |  | NEW |  |  | 0 |  |  | 0 | AllplanAttributes - ash_W_Trockenbau_Qualitäten: 9; Sicherheitsklasse: -
 | H2 Ebene +1 | WI-STB | 1163Wa 0812437344 | yes | Codetext | m² | Zimmer- und Holzbauarbeiten | Wand | Außenwand 1-Schalig | WI-STB | 0 | A | 3.75 | 1163HWa0812428691 | NEW | yes | no | REI 60-A1 - D,s2-d0 /A1 | 0 | no | 0 | no | Codetext | AllplanAttributes - Positionsnummer_Text: U100
 | H2 Ebene +1 | WI-LB | 1163Wa 0812845633 | yes | Codetext | m² | Trockenbauarbeiten | Wand | Außenwand 1-Schalig | WI-LB | 0 | A | 3.75 | 1163HWa0812428691 | NEW | no | no | REI 60-A1 - D,s2-d0 /A1 | 0 | no | 0 | no | Codetext | AllplanAttributes - ash_W_Trockenbau_Qualitäten: 9; Positionsnummer_Text: U100
 | H2 Ebene +1 | WI-STB | 1163Wa 0812439603 | yes | Codetext | m² | Zimmer- und Holzbauarbeiten | Wand | Außenwand 1-Schalig | WI-STB | 0 | A | 3.75 | 1163HWa0812428690 | NEW | yes | no | REI 60-A1 - D,s2-d0 /A1 | 0 | no | 0 | no | Codetext | AllplanAttributes - Ortscode_Geschoßbezeichnung: E01; Positionsnummer_Text: U100
 | H2 Ebene +1 | WA-STB | 1163Wa 0812437668 | yes | Codetext | m² | Zimmer- und Holzbauarbeiten | Wand | Außenwand 1-Schalig | WA-STB | 0 | A | 3.75 | 1163HWa0812425612 | NEW | yes | no | REI 60-A1 - D,s2-d0 /A1 | 0 | no | 0 | no | Codetext | AllplanAttributes - Ortscode_Geschoßbezeichnung: E01; Positionsnummer_Text: U100
 | H2 Ebene +1 | WI-LB | 1163Wa 0814490667 | yes | Codetext | m² | Trockenbauarbeiten | Wand | Innenwand 1-Schalig | WI-LB | 0 | A | 3.75 | 1163HWa0812705301 | NEW | no | no | 0 | 0 | no |  | no | Codetext | AllplanAttributes - W_Deckenanschluss: Gleitender Deckenanschluss Fall 01; Positionsnummer_Text: U100
 | H2 Ebene +1 | WI-LB | 1163Wa 0814491175 | yes | Codetext | m² | Trockenbauarbeiten | Wand | Innenwand 1-Schalig | WI-LB | 0 | A | 3.75 | 1163HWa0812496570 | NEW | no | no | REI 30-A1 - D,s2-d0 +A1 | 0 | no | 47 | no | Codetext | AllplanAttributes - W_Deckenanschluss: Gleitender Deckenanschluss Fall 01; ash_W_Trockenbau_Qualitäten: 1a; Positionsnummer_Text: U100
 | H2 Ebene +1 | WI-LB | 1163Wa 0813714398 | yes | Codetext | m² | Trockenbauarbeiten | Wand | Innenwand 1-Schalig | WI-LB | 0 | A | 3.75 | 1163HWa0813714397 | NEW |  | no | 0 | 0 | no | 47 | no | Codetext | AllplanAttributes - W_Deckenanschluss: Gleitender Deckenanschluss Fall 01; ash_W_Trockenbau_Qualitäten: 1a; Positionsnummer_Text: U100
 | H2 Ebene +1 | WI-LB | 1163Wa 0814491401 | yes | Codetext | m² | Trockenbauarbeiten | Wand | Innenwand 1-Schalig | WI-LB | 0 | A | 3.75 | 1163HWa0813714673 | NEW |  | no | 0 | 0 | no | 47 | no | Codetext | AllplanAttributes - W_Deckenanschluss: Gleitender Deckenanschluss Fall 01; ash_W_Trockenbau_Qualitäten: 1a; Positionsnummer_Text: U100
 | H2 Ebene +1 | WI-LB | 1163Wa 0812441637 |  | Codetext | m² | Trockenbauarbeiten | Wand |  |  | 0 | A | 3.75 | 1163HWa0812440898 | NEW | no | no | 0 | 0 | no | 0 | no | Codetext | AllplanAttributes - Ortscode_Geschoßbezeichnung: E01; W_Deckenanschluss: Gleitender Deckenanschluss Fall 03; ash_W_Trockenbau_Qualitäten: 10a; Positionsnummer_Text: U100
 | H2 Ebene +1 | WI-LB | 1163Wa 0812441694 |  | Codetext | m² | Trockenbauarbeiten | Wand |  |  | 0 | A | 3.75 | 1163HWa0812440900 | NEW | no | no | 0 | 0 | no | 0 | no | Codetext | AllplanAttributes - Ortscode_Geschoßbezeichnung: E01; W_Deckenanschluss: Gleitender Deckenanschluss Fall 03; ash_W_Trockenbau_Qualitäten: 10a; Positionsnummer_Text: U100
 | H2 Ebene +1 | WI-LB | 1163Wa 0812441634 |  | Codetext | m² | Trockenbauarbeiten | Wand |  |  | 0 | A | 3.75 | 1163HWa0812440914 | NEW | no | no | 0 | 0 | no | 0 | no | Codetext | AllplanAttributes - Ortscode_Geschoßbezeichnung: E01; W_Deckenanschluss: Gleitender Deckenanschluss Fall 03; ash_W_Trockenbau_Qualitäten: 10a; Positionsnummer_Text: U100
 | H2 Ebene +1 | WI-LB | 1163Wa 0812441697 |  | Codetext | m² | Trockenbauarbeiten | Wand |  |  | 0 | A | 3.75 | 1163HWa0812440915 | NEW | no | no | 0 | 0 | no | 0 | no | Codetext | AllplanAttributes - Ortscode_Geschoßbezeichnung: E01; W_Deckenanschluss: Gleitender Deckenanschluss Fall 03; ash_W_Trockenbau_Qualitäten: 10a; Positionsnummer_Text: U100
 | H2 Ebene +1 | WI-LB | 1163Wa 0812441870 |  | Codetext | m² | Trockenbauarbeiten | Wand |  |  | 0 | A | 3.75 | 1163HWa0812441736 | NEW | no | no | 0 | 0 | no | 0 | no | Codetext | AllplanAttributes - Ortscode_Geschoßbezeichnung: E01; W_Deckenanschluss: Gleitender Deckenanschluss Fall 03; ash_W_Trockenbau_Qualitäten: 10a; Positionsnummer_Text: U100
 | H2 Ebene +1 | WI-LB | 1163Wa 0812443217 | yes | Codetext | m² | Trockenbauarbeiten | Wand | Innenwand 1-Schalig | WI-LB | 0 | A | 3.75 | 1163HWa0812435326 | NEW |  | no | 0 | 0 | no | 47 | no | Codetext | AllplanAttributes - Ortscode_Geschoßbezeichnung: E01; W_Deckenanschluss: Gleitender Deckenanschluss Fall 01; ash_W_Trockenbau_Qualitäten: 1b; Positionsnummer_Text: U100
 | H2 Ebene +1 | WI-LB | 1163Wa 0812441735 |  | Codetext | m² | Trockenbauarbeiten | Wand | Innenwand 1-Schalig | WI-LB | 0 | A | 3.75 | 1163HWa0812440936 | NEW |  | no | REI 30 | 0 | no | 47 | no | Codetext | AllplanAttributes - Ortscode_Geschoßbezeichnung: E01; W_Deckenanschluss: Gleitender Deckenanschluss Fall 03; ash_W_Trockenbau_Qualitäten: 1c; Positionsnummer_Text: U100
 | H2 Ebene +1 | WI-LB | 1163Wa 0812441662 |  | Codetext | m² | Trockenbauarbeiten | Wand |  |  | 0 | A | 3.75 | 1163HWa0812440937 | NEW |  | no | 0 | 0 | no | 47 | no | Codetext | AllplanAttributes - Ortscode_Geschoßbezeichnung: E01; W_Deckenanschluss: Gleitender Deckenanschluss Fall 03; ash_W_Trockenbau_Qualitäten: 1c; Positionsnummer_Text: U100
 | H2 Ebene +1 | WI-LB | 1163Wa 0812441648 |  | Codetext | m² | Trockenbauarbeiten | Wand | Innenwand 1-Schalig | WI-LB | 0 | A | 3.75 | 1163HWa0812440928 | NEW |  | no | REI 30 | 0 | no | 47 | no | Codetext | AllplanAttributes - Ortscode_Geschoßbezeichnung: E01; W_Deckenanschluss: Gleitender Deckenanschluss Fall 03; ash_W_Trockenbau_Qualitäten: 1c; Positionsnummer_Text: U100
 | H2 Ebene +1 | WI-LB | 1163Wa 0812441658 |  | Codetext | m² | Trockenbauarbeiten | Wand |  |  | 0 | A | 3.75 | 1163HWa0812440934 | NEW |  | no | 0 | 0 | no | 47 | no | Codetext | AllplanAttributes - Ortscode_Geschoßbezeichnung: E01; W_Deckenanschluss: Gleitender Deckenanschluss Fall 03; ash_W_Trockenbau_Qualitäten: 1c; Positionsnummer_Text: U100
 | H2 Ebene +1 | WI-LB | 1163Wa 0812441644 |  | Codetext | m² | Trockenbauarbeiten | Wand | Innenwand 1-Schalig | WI-LB | 0 | A | 3.75 | 1163HWa0812440932 | NEW |  | no | REI 30 | 0 | no | 47 | no | Codetext | AllplanAttributes - Ortscode_Geschoßbezeichnung: E01; W_Deckenanschluss: Gleitender Deckenanschluss Fall 03; ash_W_Trockenbau_Qualitäten: 1c; Positionsnummer_Text: U100
 | H2 Ebene +1 | WI-HW 60 | 1163Wa 0812447127 | yes | Codetext | m² | Zimmer- und Holzbauarbeiten | Wand | Innenwand 1-Schalig | WI-HW 60 | 0 | A | 3.75 | 1163HWa0812430569 | NEW | no | no | REI 60-A1 - D,s2-d0 +A1 | 0 | no | 52 | no | Codetext | AllplanAttributes - Positionsnummer_Text: U100
 | H2 Ebene +1 | WI-LB | 1163Wa 0813783446 | yes | Codetext | m² | Trockenbauarbeiten | Wand | Innenwand 1-Schalig | WI-LB | 0 | A | 3.75 | 1163HWa0812430569 | NEW | no | no | REI 60-A1 - D,s2-d0 /A1 | 0 | no | 52 | no | Codetext | AllplanAttributes - ash_W_Trockenbau_Qualitäten: 6; Positionsnummer_Text: U100
 | H2 Ebene +1 | WI-HW 60 | 1163Wa 0814186991 | yes | Codetext | m² | Zimmer- und Holzbauarbeiten | Wand | Innenwand 1-Schalig | WI-HW 60 | 0 | A | 3.75 | 1163HWa0812430562 | NEW | no | no | REI 60-A1 - D,s2-d0 +A1 | 0 | no | 52 | no | Codetext | AllplanAttributes - ash W_laufende Nr. Statik: 3 (W 3.0); Positionsnummer_Text: U100
 | H2 Ebene +1 | WI-LB | 1163Wa 0814186990 | yes | Codetext | m² | Trockenbauarbeiten | Wand | Innenwand 1-Schalig | WI-LB | 0 | A | 3.75 | 1163HWa0812430562 | NEW | no | no | REI 60-A1 - D,s2-d0 /A1 | 0 | no | 52 | no | Codetext | AllplanAttributes - ash_W_Trockenbau_Qualitäten: 6; Positionsnummer_Text: U100
WV 1.1 | H2 Ebene +1 |  | 1163Sma0814505241 |  | VUK1 - Hängeschrank | St | Trockenbauarbeiten | SmartPart | WV 1.1 |  |  |  | 3.75 |  |  |  |  | - | AllplanAttributes - Text1: WA2008; UK: 0 m; OK: 0 m; V6: 0 m; V7: 0 m; V8: 0 m; V9: 0; Länge: 2.2 m; Dicke: 0.025 m; Höhe: 0.2 m; Programmversion: 3.1; Text3: 0; Plugin_Bezeichnung: MainObject; Plugin_Objektname: SmartPartCompressed; Version: 1.1; Abstand_Öffn_Unten: 6.1 m; ash T_Feuchtebeständigkeit: nein; Feuerwiderstandsklasse~: nein
WV 1.1 | H2 Ebene +1 |  | 1163Sma0814505326 |  | VUK1 - Hängeschrank | St | Trockenbauarbeiten | SmartPart | WV 1.1 |  |  |  | 3.75 |  |  |  |  | - | AllplanAttributes - Text1: WA2008; UK: 0 m; OK: 0 m; V6: 0 m; V7: 0 m; V8: 0 m; V9: 0; Länge: 4.65 m; Dicke: 0.025 m; Höhe: 0.2 m; Programmversion: 3.1; Text3: 0; Plugin_Bezeichnung: MainObject; Plugin_Objektname: SmartPartCompressed; Version: 1.1; Abstand_Öffn_Unten: 6.1 m; ash T_Feuchtebeständigkeit: nein; Feuerwiderstandsklasse~: nein
WV 1.1 | H2 Ebene +1 |  | 1163Sma0814505340 |  | VUK1 - Hängeschrank | St | Trockenbauarbeiten | SmartPart | WV 1.1 |  |  |  | 3.75 |  |  |  |  | - | AllplanAttributes - Text1: WA2008; UK: 0 m; OK: 0 m; V6: 0 m; V7: 0 m; V8: 0 m; V9: 0; Länge: 2.2 m; Dicke: 0.025 m; Höhe: 0.2 m; Programmversion: 3.1; Text3: 0; Plugin_Bezeichnung: MainObject; Plugin_Objektname: SmartPartCompressed; Version: 1.1; Abstand_Öffn_Unten: 6.1 m; ash T_Feuchtebeständigkeit: nein; Feuerwiderstandsklasse~: nein
WV 1.1 | H2 Ebene +1 |  | 1163Sma0814505833 |  | VUK1 - Hängeschrank | St | Trockenbauarbeiten | SmartPart | WV 1.1 |  |  |  | 3.75 |  |  |  |  | - | AllplanAttributes - Text1: WA2018; UK: 0 m; OK: 0 m; V6: 0 m; V7: 0 m; V8: 0 m; V9: 0; Länge: 3.76 m; Dicke: 0.025 m; Höhe: 0.2 m; Programmversion: 3.1; Text3: 0; Plugin_Bezeichnung: MainObject; Plugin_Objektname: SmartPartCompressed; Version: 1.1; Abstand_Öffn_Unten: 6.1 m; ash T_Feuchtebeständigkeit: nein; Feuerwiderstandsklasse~: nein
WV 1.1 | H2 Ebene +1 |  | 1163Sma0814505872 |  | VUK1 - Desinfektionsmittelspender | St | Trockenbauarbeiten | SmartPart | WV 1.1 |  |  |  | 3.75 |  |  |  |  | - | AllplanAttributes - Text1: WA2018; UK: 0 m; OK: 0 m; V6: 0 m; V7: 0 m; V8: 0 m; V9: 0; Länge: 0.2 m; Dicke: 0.025 m; Höhe: 0.3 m; Programmversion: 3.1; Text3: 0; Plugin_Bezeichnung: MainObject; Plugin_Objektname: SmartPartCompressed; Version: 1.1; Abstand_Öffn_Unten: 5.01 m; ash T_Feuchtebeständigkeit: nein; Feuerwiderstandsklasse~: nein
WV 1.1 | H2 Ebene +1 |  | 1163Sma0814506001 |  | VUK1 - Desinfektionsmittelspender | St | Trockenbauarbeiten | SmartPart | WV 1.1 |  |  |  | 3.75 |  |  |  |  | - | AllplanAttributes - Text1: WA2016; UK: 0 m; OK: 0 m; V6: 0 m; V7: 0 m; V8: 0 m; V9: 0; Länge: 0.2 m; Dicke: 0.025 m; Höhe: 0.3 m; Programmversion: 3.1; Text3: 0; Plugin_Bezeichnung: MainObject; Plugin_Objektname: SmartPartCompressed; Version: 1.1; Abstand_Öffn_Unten: 5.01 m; ash T_Feuchtebeständigkeit: nein; Feuerwiderstandsklasse~: nein
WV 1.1 | H2 Ebene +1 |  | 1163Sma0814506216 |  | VUK1 - Haltegriff | St | Trockenbauarbeiten | SmartPart | WV 1.1 |  |  |  | 3.75 |  |  |  |  | - | AllplanAttributes - Text1: WA2018; UK: 0 m; OK: 0 m; V6: 0 m; V7: 0 m; V8: 0 m; V9: 0; Länge: 1.6 m; Dicke: 0.025 m; Höhe: 0.2 m; Programmversion: 3.1; Text3: 0; Plugin_Bezeichnung: MainObject; Plugin_Objektname: SmartPartCompressed; Version: 1.1; Abstand_Öffn_Unten: 5.3 m; ash T_Feuchtebeständigkeit: nein; Feuerwiderstandsklasse~: nein
WV 1.1 | H2 Ebene +1 |  | 1163Sma0814506527 |  | VUK1 - Desinfektionsmittelspender | St | Trockenbauarbeiten | SmartPart | WV 1.1 |  |  |  | 3.75 |  |  |  |  | - | AllplanAttributes - Text1: WA2018; UK: 0 m; OK: 0 m; V6: 0 m; V7: 0 m; V8: 0 m; V9: 0; Länge: 0.2 m; Dicke: 0.025 m; Höhe: 0.3 m; Programmversion: 3.1; Text3: 0; Plugin_Bezeichnung: MainObject; Plugin_Objektname: SmartPartCompressed; Version: 1.1; Abstand_Öffn_Unten: 5.01 m; ash T_Feuchtebeständigkeit: nein; Feuerwiderstandsklasse~: nein
WV 1.1 | H2 Ebene +1 |  | 1163Sma0814506514 |  | VUK1 - Hängeschrank | St | Trockenbauarbeiten | SmartPart | WV 1.1 |  |  |  | 3.75 |  |  |  |  | - | AllplanAttributes - Text1: WA2018; UK: 0 m; OK: 0 m; V6: 0 m; V7: 0 m; V8: 0 m; V9: 0; Länge: 5.74 m; Dicke: 0.025 m; Höhe: 0.2 m; Programmversion: 3.1; Text3: 0; Plugin_Bezeichnung: MainObject; Plugin_Objektname: SmartPartCompressed; Version: 1.1; Abstand_Öffn_Unten: 6.1 m; ash T_Feuchtebeständigkeit: nein; Feuerwiderstandsklasse~: nein
WV 1.1 | H2 Ebene +1 |  | 1163Sma0814506985 |  | VUK1 - Desinfektionsmittelspender | St | Trockenbauarbeiten | SmartPart | WV 1.1 |  |  |  | 3.75 |  |  |  |  | - | AllplanAttributes - Text1: WA2020; UK: 0 m; OK: 0 m; V6: 0 m; V7: 0 m; V8: 0 m; V9: 0; Länge: 0.2 m; Dicke: 0.025 m; Höhe: 0.3 m; Programmversion: 3.1; Text3: 0; Plugin_Bezeichnung: MainObject; Plugin_Objektname: SmartPartCompressed; Version: 1.1; Abstand_Öffn_Unten: 5.01 m; ash T_Feuchtebeständigkeit: nein; Feuerwiderstandsklasse~: nein
 | H2 Ebene +1 | WI-LB | 1163Wa 0814511197 | yes | Codetext | m² | Trockenbauarbeiten | Wand | Innenwand 1-Schalig | WI-LB | 0 | A | 3.75 | 1163HWa0812839978 | NEW | no | no | REI 60-A1 - D,s2-d0 /A1 | 0 | no |  | no | Codetext | AllplanAttributes - Positionsnummer_Text: U100
 | H2 Ebene +1 | WI-LB | 1163Wa 0812516237 | yes | Codetext | m² | Trockenbauarbeiten | Wand | Innenwand 1-Schalig | WI-LB | 0 | A | 3.75 | 1163HWa0812516229 | NEW |  | no | 0 | 0 | no | 47 | no | Codetext | AllplanAttributes - W_Deckenanschluss: Gleitender Deckenanschluss Fall 01; ash_W_Trockenbau_Qualitäten: 1e; Positionsnummer_Text: U100
 | H2 Ebene +1 | WI-LB | 1163Wa 0814511864 | yes | Codetext | m² | Trockenbauarbeiten | Wand | Innenwand 1-Schalig | WI-LB | 0 | A | 3.75 | 1163HWa0812840037 | NEW | no | no | REI 60-A1 - D,s2-d0 /A1 | 0 | no |  | no | Codetext | AllplanAttributes - ash_W_Trockenbau_Qualitäten: 9; Positionsnummer_Text: U100
 | H2 Ebene +1 | WI-LB | 1163Wa 0814511875 | yes | Codetext | m² | Trockenbauarbeiten | Wand | Innenwand 1-Schalig | WI-LB | 0 | A | 3.75 | 1163HWa0812840037 | NEW | no | no | REI 60-A1 - D,s2-d0 /A1 | 0 | no |  | no | Codetext | AllplanAttributes - ash_W_Trockenbau_Qualitäten: 9; Positionsnummer_Text: U100
 | H2 Ebene +1 | WI-HW 60 | 1163Wa 0814485051 | yes | Codetext | m² | Zimmer- und Holzbauarbeiten | Wand | Innenwand 1-Schalig | WI-HW 60 | 0 | A | 3.75 | 1163HWa0812440566 | NEW | no | no | REI 60-A1 - D,s2-d0 +A1 | 0 | no | 47 | no | Codetext | AllplanAttributes - ash W_laufende Nr. Statik: 1 (W 1.0/ 1.1/ 1.2); Positionsnummer_Text: U100
 | H2 Ebene +1 | WI-LB | 1163Wa 0814512256 | yes | Codetext | m² | Trockenbauarbeiten | Wand | Innenwand 1-Schalig | WI-LB | 0 | A | 3.75 | 1163HWa0812841598 | NEW | no | no | REI 60-A1 - D,s2-d0 /A1 | 0 | no | 0 | no | Codetext | AllplanAttributes - ash_W_Trockenbau_Qualitäten: 9; Positionsnummer_Text: U100
 | H2 Ebene +1 | WI-LB | 1163Wa 0814512268 | yes | Codetext | m² | Trockenbauarbeiten | Wand | Innenwand 1-Schalig | WI-LB | 0 | A | 3.75 | 1163HWa0812841598 | NEW | no | no | REI 60-A1 - D,s2-d0 /A1 | 0 | no | 0 | no | Codetext | AllplanAttributes - ash_W_Trockenbau_Qualitäten: 9; Positionsnummer_Text: U100
 | H2 Ebene +1 | WI-LB | 1163Wa 0814512282 | yes | Codetext | m² | Trockenbauarbeiten | Wand | Innenwand 1-Schalig | WI-LB | 0 | A | 3.75 | 1163HWa0812841598 | NEW | no | no | REI 60-A1 - D,s2-d0 /A1 | 0 | no | 0 | no | Codetext | AllplanAttributes - ash_W_Trockenbau_Qualitäten: 9; Positionsnummer_Text: U100
 | H2 Ebene +1 | WI-LB | 1163Wa 0814512294 | yes | Codetext | m² | Trockenbauarbeiten | Wand | Innenwand 1-Schalig | WI-LB | 0 | A | 3.75 | 1163HWa0812841598 | NEW | no | no | REI 60-A1 - D,s2-d0 /A1 | 0 | no | 0 | no | Codetext | AllplanAttributes - ash_W_Trockenbau_Qualitäten: 9; Positionsnummer_Text: U100
 | H2 Ebene +1 | WI-LB | 1163Wa 0814512303 | yes | Codetext | m² | Trockenbauarbeiten | Wand | Innenwand 1-Schalig | WI-LB | 0 | A | 3.75 | 1163HWa0812841598 | NEW | no | no | REI 60-A1 - D,s2-d0 /A1 | 0 | no |  | no | Codetext | AllplanAttributes - ash_W_Trockenbau_Qualitäten: 9; Positionsnummer_Text: U100
 | H2 Ebene +1 | WI-LB | 1163Wa 0814512312 | yes | Codetext | m² | Trockenbauarbeiten | Wand | Innenwand 1-Schalig | WI-LB | 0 | A | 3.75 | 1163HWa0812841598 | NEW | no | no | REI 60-A1 - D,s2-d0 /A1 | 0 | no |  | no | Codetext | AllplanAttributes - ash_W_Trockenbau_Qualitäten: 9; Positionsnummer_Text: U100
 | H2 Ebene +1 | WI-LB | 1163Wa 0812842157 | yes | Codetext | m² | Trockenbauarbeiten | Wand | Innenwand 1-Schalig | WI-LB | 0 | A | 3.75 | 1163HWa0812842156 | NEW | no | no | REI 60-A1 - D,s2-d0 /A1 | 0 | no | 0 | no | Codetext | AllplanAttributes - Ortscode_Geschoßbezeichnung: E01; ash_W_Trockenbau_Qualitäten: 9; Positionsnummer_Text: U100
 | H2 Ebene +1 | WI-LB | 1163Wa 0812442491 |  | Codetext | m² | Trockenbauarbeiten | Wand |  |  | 0 | A | 3.75 | 1163HWa0812440946 | NEW | no | no | 0 | 0 | no | 0 | no | Codetext | AllplanAttributes - Ortscode_Geschoßbezeichnung: E01; W_Deckenanschluss: Gleitender Deckenanschluss Fall 03; ash_W_Trockenbau_Qualitäten: 10a; Positionsnummer_Text: U100
 | H2 Ebene +1 | WI-HW 60 | 1163Wa 0814518972 | yes | Codetext | m² | Zimmer- und Holzbauarbeiten | Wand | Innenwand 1-Schalig | WI-HW 60 | 0 | A | 3.75 | 1163HWa0812440544 | NEW | no | no | REI 30 | 0 | no | 47 | no | Codetext | AllplanAttributes - ash W_laufende Nr. Statik: 1 (W 1.0/ 1.1/ 1.2); Positionsnummer_Text: U100
 | H2 Ebene +1 | WI-LB | 1163Wa 0814518977 | yes | Codetext | m² | Trockenbauarbeiten | Wand | Innenwand 1-Schalig | WI-LB | 0 | A | 3.75 | 1163HWa0812440544 | NEW | no | no | REI 30-A1 - D,s2-d0 +A1 | 0 | no | 47 | no | Codetext | AllplanAttributes - ash_W_Trockenbau_Qualitäten: 6; Sicherheitsklasse: -; Positionsnummer_Text: U100
 | H2 Ebene +1 | WI-HW 60 | 1163Wa 0814519943 | yes | Codetext | m² | Zimmer- und Holzbauarbeiten | Wand | Innenwand 1-Schalig | WI-HW 60 | 0 | A | 3.75 | 1163HWa0812440544 | NEW | no | no | REI 30 | 0 | no | 47 | no | Codetext | AllplanAttributes - ash W_laufende Nr. Statik: 1 (W 1.0/ 1.1/ 1.2); Positionsnummer_Text: U100
 | H2 Ebene +1 | WI-LB | 1163Wa 0814519942 | yes | Codetext | m² | Trockenbauarbeiten | Wand | Innenwand 1-Schalig | WI-LB | 0 | A | 3.75 | 1163HWa0812440544 | NEW | no | no | REI 30-A1 - D,s2-d0 +A1 | 0 | no | 47 | no | Codetext | AllplanAttributes - ash_W_Trockenbau_Qualitäten: 6; Sicherheitsklasse: -; Positionsnummer_Text: U100
 | H2 Ebene +1 | WI-HW 60 | 1163Wa 0814520615 | yes | Codetext | m² | Zimmer- und Holzbauarbeiten | Wand | Innenwand 1-Schalig | WI-HW 60 | 0 | A | 3.75 | 1163HWa0812440544 | NEW | no | no | REI 30 | 0 | no | 47 | no | Codetext | AllplanAttributes - ash W_laufende Nr. Statik: 1 (W 1.0/ 1.1/ 1.2); Positionsnummer_Text: U100
 | H2 Ebene +1 | WI-LB | 1163Wa 0814520614 | yes | Codetext | m² | Trockenbauarbeiten | Wand | Innenwand 1-Schalig | WI-LB | 0 | A | 3.75 | 1163HWa0812440544 | NEW | no | no | REI 30-A1 - D,s2-d0 +A1 | 0 | no | 47 | no | Codetext | AllplanAttributes - ash_W_Trockenbau_Qualitäten: 6; Sicherheitsklasse: -; Positionsnummer_Text: U100
 | H2 Ebene +1 | WI-HW 60 | 1163Wa 0814520683 | yes | Codetext | m² | Zimmer- und Holzbauarbeiten | Wand | Innenwand 1-Schalig | WI-HW 60 | 0 | A | 3.75 | 1163HWa0812440544 | NEW |  | no | REI 30 | 0 | no | 47 | no | Codetext | AllplanAttributes - ash W_laufende Nr. Statik: 1 (W 1.0/ 1.1/ 1.2); Positionsnummer_Text: U100
 | H2 Ebene +1 | WI-HW 60 | 1163Wa 0814520694 | yes | Codetext | m² | Zimmer- und Holzbauarbeiten | Wand | Innenwand 1-Schalig | WI-HW 60 | 0 | A | 3.75 | 1163HWa0812440544 | NEW |  | no | REI 30 | 0 | no | 47 | no | Codetext | AllplanAttributes - ash W_laufende Nr. Statik: 1 (W 1.0/ 1.1/ 1.2); Positionsnummer_Text: U100
 | H2 Ebene +1 | WI-HW 60 | 1163Wa 0814520705 | yes | Codetext | m² | Zimmer- und Holzbauarbeiten | Wand | Innenwand 1-Schalig | WI-HW 60 | 0 | A | 3.75 | 1163HWa0812440544 | NEW |  | no | REI 30 | 0 | no | 47 | no | Codetext | AllplanAttributes - ash W_laufende Nr. Statik: 1 (W 1.0/ 1.1/ 1.2); Positionsnummer_Text: U100
 | H2 Ebene +1 | WI-LB | 1163Wa 0812441627 | yes | Codetext | m² | Trockenbauarbeiten | Wand | Innenwand 1-Schalig | WI-LB | 0 | A | 3.75 | 1163HWa0812440911 | NEW | no | no | 0 | 0 | no | 0 | no | Codetext | AllplanAttributes - W_Deckenanschluss: Gleitender Deckenanschluss Fall 03; ash_W_Trockenbau_Qualitäten: 1b; Positionsnummer_Text: U100
 | H2 Ebene +1 | WI-LB | 1163Wa 0812441668 |  | Codetext | m² | Trockenbauarbeiten | Wand |  |  | 0 | A | 3.75 | 1163HWa0812440913 | NEW | no | no | 0 | 0 | no | 0 | no | Codetext | AllplanAttributes - Ortscode_Geschoßbezeichnung: E01; W_Deckenanschluss: Gleitender Deckenanschluss Fall 03; ash_W_Trockenbau_Qualitäten: 10a; Positionsnummer_Text: U100
 | H2 Ebene +1 | WI-LB | 1163Wa 0812441625 | yes | Codetext | m² | Trockenbauarbeiten | Wand | Innenwand 1-Schalig | WI-LB | 0 | A | 3.75 | 1163HWa0812440879 | NEW | no | no | 0 | 0 | no | 0 | no | Codetext | AllplanAttributes - W_Deckenanschluss: Gleitender Deckenanschluss Fall 03; ash_W_Trockenbau_Qualitäten: 1b; Positionsnummer_Text: U100
 | H2 Ebene +1 | WI-LB | 1163Wa 0812441666 |  | Codetext | m² | Trockenbauarbeiten | Wand |  |  | 0 | A | 3.75 | 1163HWa0812440899 | NEW | no | no | 0 | 0 | no | 0 | no | Codetext | AllplanAttributes - Ortscode_Geschoßbezeichnung: E01; W_Deckenanschluss: Gleitender Deckenanschluss Fall 03; ash_W_Trockenbau_Qualitäten: 10a; Positionsnummer_Text: U100
 | H2 Ebene +1 | WI-LB | 1163Wa 0813666053 | yes | Codetext | m² | Trockenbauarbeiten | Wand | Innenwand 1-Schalig | WI-LB | 0 | A | 3.75 | 1163HWa0813666050 | NEW | no | no | 0 | 0 | no | 0 | no | Codetext | AllplanAttributes - W_Deckenanschluss: Gleitender Deckenanschluss Fall 03; ash_W_Trockenbau_Qualitäten: 1b; Positionsnummer_Text: U100
 | H2 Ebene +1 | WI-LB | 1163Wa 0812441623 | yes | Codetext | m² | Trockenbauarbeiten | Wand | Innenwand 1-Schalig | WI-LB | 0 | A | 3.75 | 1163HWa0812440881 | NEW | no | no | 0 | 0 | no | 0 | no | Codetext | AllplanAttributes - W_Deckenanschluss: Gleitender Deckenanschluss Fall 03; ash_W_Trockenbau_Qualitäten: 1b; Positionsnummer_Text: U100
 | H2 Ebene +1 | WI-LB | 1163Wa 0812441664 |  | Codetext | m² | Trockenbauarbeiten | Wand |  |  | 0 | A | 3.75 | 1163HWa0812440883 | NEW | no | no | 0 | 0 | no | 0 | no | Codetext | AllplanAttributes - Ortscode_Geschoßbezeichnung: E01; W_Deckenanschluss: Gleitender Deckenanschluss Fall 03; ash_W_Trockenbau_Qualitäten: 10a; Positionsnummer_Text: U100
 | H2 Ebene +1 | WI-HW 60 | 1163Wa 0814537200 | yes | Codetext | m² | Zimmer- und Holzbauarbeiten | Wand | Innenwand 1-Schalig | WI-HW 60 | 0 | A | 3.75 | 1163HWa0812441885 | NEW | no | no | REI 30-A1 - D,s2-d0 +A1 | 0 | no | 0 | no | Codetext | AllplanAttributes - ash W_laufende Nr. Statik: 3 (W 3.0); Positionsnummer_Text: U100
 | H2 Ebene +1 | WI-LB | 1163Wa 0814537223 | yes | Codetext | m² | Trockenbauarbeiten | Wand | Innenwand 1-Schalig | WI-LB | 0 | A | 3.75 | 1163HWa0812442703 | NEW | no | no | REI 60-A1 - D,s2-d0 +A1 | 0 | no | 0 | no | Codetext | AllplanAttributes - W_Deckenanschluss: Gleitender Deckenanschluss Fall 01; ash_W_Trockenbau_Qualitäten: 1b; Positionsnummer_Text: U100
 | H2 Ebene +1 | WI-HW 60 | 1163Wa 0812443620 | yes | Codetext | m² | Zimmer- und Holzbauarbeiten | Wand | Innenwand 1-Schalig | WI-HW 60 | 0 | A | 3.75 | 1163HWa0812440865 | NEW | yes | no | REI 30-A1 - D,s2-d0 +A1 | 0 | no | 0 | no | Codetext | AllplanAttributes - Ortscode_Geschoßbezeichnung: E01; ash W_laufende Nr. Statik: 3 (W 3.0); Positionsnummer_Text: U100
 | H2 Ebene +1 | WI-HW 60 | 1163Wa 0814550785 | yes | Codetext | m² | Zimmer- und Holzbauarbeiten | Wand | Innenwand 1-Schalig | WI-HW 60 | 0 | A | 3.75 | 1163HWa0812654445 | NEW | yes | no | REI 60-A1 - D,s2-d0 /A1 | 0 | no | 0 | no | Codetext | AllplanAttributes - ash W_laufende Nr. Statik: 3 (W 3.0); Positionsnummer_Text: U100
 | H2 Ebene +1 | WI-LB | 1163Wa 0812444061 | yes | Codetext | m² | Trockenbauarbeiten | Wand | Innenwand 1-Schalig | WI-LB | 0 | A | 3.75 | 1163HWa0812442712 | NEW | no | no | REI 30-A1 - D,s2-d0 +A1 | 0 | no | 47 | no | Codetext | AllplanAttributes - ash_W_Trockenbau_Qualitäten: 8; Sicherheitsklasse: -; Positionsnummer_Text: U100
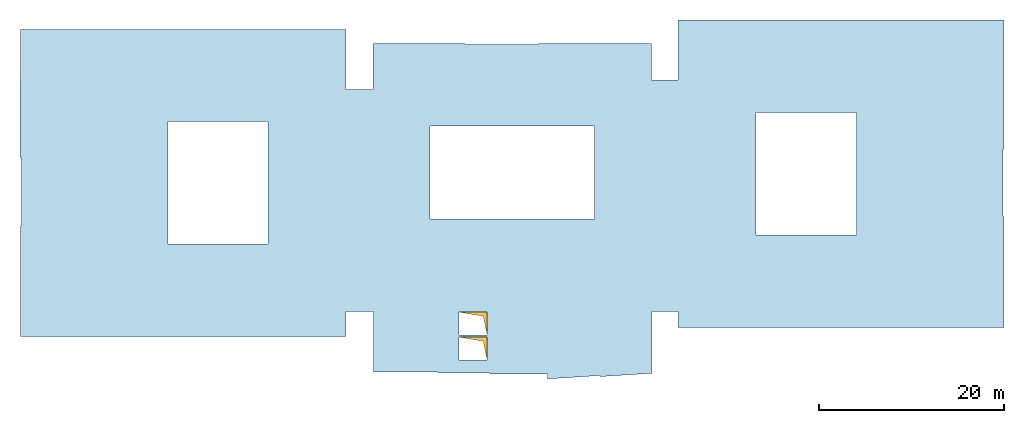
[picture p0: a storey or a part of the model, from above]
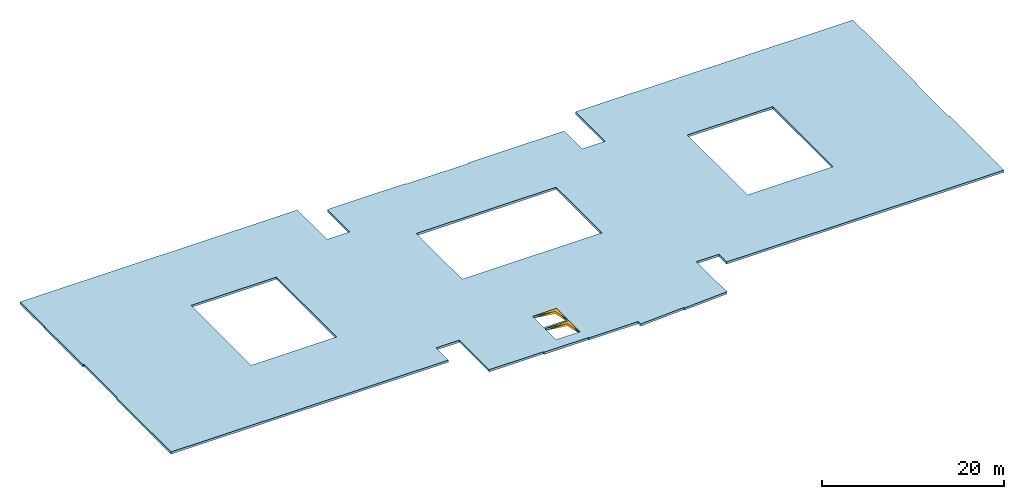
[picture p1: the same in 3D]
Properties of the parts of a building model (IFC4), part 65 of 80

# IfcWall (6826)
Name | In | Material | Allright_Bauteil_ID | 2D Interaktion | Codetext | Abrechnungsart | Gewerk | Objektname | Bezeichnung | AllplanAttributes, Material | Typ = SurfaceSpreadOfFlame | Brandschutzklasse | OKFF | P_ID | Status | LoadBearing | IsExternal | FireRating | ThermalTransmittance (W/K/m2) | Combustible | AcousticRating | Compartmentation | Reference
 | H2 Ebene +1 | Installationsraum | 1163Wa 0813775742 | yes | Codetext | m² | Trockenbauarbeiten | Wand | Innenwand 1-Schalig | Installationsraum | 0 | A | 3.75 | 1163HWa0812442712 | NEW | no | no | 0 | 0 | no | 47 | no | Codetext | AllplanAttributes - Sicherheitsklasse: -; Positionsnummer_Text: U100
 | H2 Ebene +1 | WI-HW 60 | 1163Wa 0813775743 | yes | Codetext | m² | Zimmer- und Holzbauarbeiten | Wand | Innenwand 1-Schalig | WI-HW 60 | 0 | A | 3.75 | 1163HWa0812442712 | NEW | no | no | REI 30-A1 - D,s2-d0 +A1 | 0 | no | 47 | no | Codetext | AllplanAttributes - Sicherheitsklasse: -; ash W_laufende Nr. Statik: 3 (W 3.0); Positionsnummer_Text: U100
 | H2 Ebene +1 | WI-HW 60 | 1163Wa 0814566315 | yes | Codetext | m² | Zimmer- und Holzbauarbeiten | Wand | Innenwand 1-Schalig | WI-HW 60 | 0 | A | 3.75 | 1163HWa0812442712 | NEW | no | no | REI 30-A1 - D,s2-d0 +A1 | 0 | no | 47 | no | Codetext | AllplanAttributes - Sicherheitsklasse: -; ash W_laufende Nr. Statik: 3 (W 3.0); Positionsnummer_Text: U100
 | H2 Ebene +1 | WI-LB | 1163Wa 0814566599 | yes | Codetext | m² | Trockenbauarbeiten | Wand | Innenwand 1-Schalig | WI-LB | 0 | A | 3.75 | 1163HWa0812443364 | NEW | no | no | REI 30-A1 - D,s2-d0 +A1 | 0 | no | 47 | no | Codetext | AllplanAttributes - W_Deckenanschluss: Gleitender Deckenanschluss Fall 01; ash_W_Trockenbau_Qualitäten: 1b; Positionsnummer_Text: U100
 | H2 Ebene +1 | WI-LB | 1163Wa 0814566611 | yes | Codetext | m² | Trockenbauarbeiten | Wand | Innenwand 1-Schalig | WI-LB | 0 | A | 3.75 | 1163HWa0812443364 | NEW | no | no | REI 30-A1 - D,s2-d0 +A1 | 0 | no | 47 | no | Codetext | AllplanAttributes - W_Deckenanschluss: Gleitender Deckenanschluss Fall 01; ash_W_Trockenbau_Qualitäten: 1b; Positionsnummer_Text: U100
 | H2 Ebene +1 | WI-LB | 1163Wa 0814566618 | yes | Codetext | m² | Trockenbauarbeiten | Wand | Innenwand 1-Schalig | WI-LB | 0 | A | 3.75 | 1163HWa0812443364 | NEW | no | no | REI 30-A1 - D,s2-d0 +A1 | 0 | no | 47 | no | Codetext | AllplanAttributes - W_Deckenanschluss: Gleitender Deckenanschluss Fall 01; ash_W_Trockenbau_Qualitäten: 1b; Positionsnummer_Text: U100
 | H2 Ebene +1 | WI-IW | 1163Wa 0814566636 | yes | Codetext | m² | Trockenbauarbeiten | Wand | Installationswand | WI-IW | 0 | A | 3.75 | 1163HWa0813672498 | NEW |  | no | 0 | 0 | no | 0 | no | Codetext | AllplanAttributes - W_Deckenanschluss: Gleitender Deckenanschluss Fall 01; Positionsnummer_Text: U100
 | H2 Ebene +1 | WI-HW 60 | 1163Wa 0812446773 | yes | Codetext | m² | Zimmer- und Holzbauarbeiten | Wand | Innenwand 1-Schalig | WI-HW 60 | 0 | A | 3.75 | 1163HWa0812444214 | NEW |  | no | REI 30 | 0 | no | 47 | no | Codetext | AllplanAttributes - ash W_laufende Nr. Statik: 1 (W 1.0/ 1.1/ 1.2); Positionsnummer_Text: U100
 | H2 Ebene +1 | WI-LB | 1163Wa 0813774669 | yes | Codetext | m² | Trockenbauarbeiten | Wand | Innenwand 1-Schalig | WI-LB | 0 | A | 3.75 | 1163HWa0812444214 | NEW |  | no | REI 30-A1 - D,s2-d0 +A1 | 0 | no | 47 | no | Codetext | AllplanAttributes - ash_W_Trockenbau_Qualitäten: 6; Sicherheitsklasse: -; Positionsnummer_Text: U100
 | H2 Ebene +1 | WI-HW 60 | 1163Wa 0814581576 | yes | Codetext | m² | Zimmer- und Holzbauarbeiten | Wand | Innenwand 1-Schalig | WI-HW 60 | 0 | A | 3.75 | 1163HWa0812444214 | NEW |  | no | REI 30 | 0 | no | 47 | no | Codetext | AllplanAttributes - ash W_laufende Nr. Statik: 1 (W 1.0/ 1.1/ 1.2); Positionsnummer_Text: U100
 | H2 Ebene +1 | WI-LB | 1163Wa 0814581792 | yes | Codetext | m² | Trockenbauarbeiten | Wand | Innenwand 1-Schalig | WI-LB | 0 | A | 3.75 | 1163HWa0812444214 | NEW |  | no | REI 30-A1 - D,s2-d0 +A1 | 0 | no | 47 | no | Codetext | AllplanAttributes - ash_W_Trockenbau_Qualitäten: 6; Sicherheitsklasse: -; Positionsnummer_Text: U100
 | H2 Ebene +1 | WI-HW 60 | 1163Wa 0814582766 | yes | Codetext | m² | Zimmer- und Holzbauarbeiten | Wand | Innenwand 1-Schalig | WI-HW 60 | 0 | A | 3.75 | 1163HWa0812444214 | NEW |  | no | REI 30 | 0 | no | 47 | no | Codetext | AllplanAttributes - ash W_laufende Nr. Statik: 1 (W 1.0/ 1.1/ 1.2); Positionsnummer_Text: U100
 | H2 Ebene +1 | WI-LB | 1163Wa 0814582765 | yes | Codetext | m² | Trockenbauarbeiten | Wand | Innenwand 1-Schalig | WI-LB | 0 | A | 3.75 | 1163HWa0812444214 | NEW |  | no | REI 30-A1 - D,s2-d0 +A1 | 0 | no | 47 | no | Codetext | AllplanAttributes - ash_W_Trockenbau_Qualitäten: 6; Sicherheitsklasse: -; Positionsnummer_Text: U100
 | H2 Ebene +1 | WI-HW 60 | 1163Wa 0814583442 | yes | Codetext | m² | Zimmer- und Holzbauarbeiten | Wand | Innenwand 1-Schalig | WI-HW 60 | 0 | A | 3.75 | 1163HWa0812444214 | NEW |  | no | REI 30 | 0 | no | 47 | no | Codetext | AllplanAttributes - ash W_laufende Nr. Statik: 1 (W 1.0/ 1.1/ 1.2); Positionsnummer_Text: U100
 | H2 Ebene +1 | WI-LB | 1163Wa 0814583441 | yes | Codetext | m² | Trockenbauarbeiten | Wand | Innenwand 1-Schalig | WI-LB | 0 | A | 3.75 | 1163HWa0812444214 | NEW |  | no | REI 30-A1 - D,s2-d0 +A1 | 0 | no | 47 | no | Codetext | AllplanAttributes - ash_W_Trockenbau_Qualitäten: 6; Sicherheitsklasse: -; Positionsnummer_Text: U100
 | H2 Ebene +1 | WI-HW 60 | 1163Wa 0814583513 | yes | Codetext | m² | Zimmer- und Holzbauarbeiten | Wand | Innenwand 1-Schalig | WI-HW 60 | 0 | A | 3.75 | 1163HWa0812444214 | NEW | no | no | REI 30 | 0 | no | 47 | no | Codetext | AllplanAttributes - ash W_laufende Nr. Statik: 1 (W 1.0/ 1.1/ 1.2); Positionsnummer_Text: U100
 | H2 Ebene +1 | WI-HW 60 | 1163Wa 0814583524 | yes | Codetext | m² | Zimmer- und Holzbauarbeiten | Wand | Innenwand 1-Schalig | WI-HW 60 | 0 | A | 3.75 | 1163HWa0812444214 | NEW | no | no | REI 30 | 0 | no | 47 | no | Codetext | AllplanAttributes - ash W_laufende Nr. Statik: 1 (W 1.0/ 1.1/ 1.2); Positionsnummer_Text: U100
 | H2 Ebene +1 | WI-HW 60 | 1163Wa 0814583535 | yes | Codetext | m² | Zimmer- und Holzbauarbeiten | Wand | Innenwand 1-Schalig | WI-HW 60 | 0 | A | 3.75 | 1163HWa0812444214 | NEW | no | no | REI 30 | 0 | no | 47 | no | Codetext | AllplanAttributes - ash W_laufende Nr. Statik: 1 (W 1.0/ 1.1/ 1.2); Positionsnummer_Text: U100
 | H2 Ebene +1 | WI-HW 60 | 1163Wa 0812446747 | yes | Codetext | m² | Zimmer- und Holzbauarbeiten | Wand | Innenwand 1-Schalig | WI-HW 60 | 0 | A | 3.75 | 1163HWa0812442199 | NEW | no | no | REI 60-A1 - D,s2-d0 +A1 | 0 | no | 47 | no | Codetext | AllplanAttributes - ash W_laufende Nr. Statik: 3 (W 3.0); Positionsnummer_Text: U100
 | H2 Ebene +1 | WI-LB | 1163Wa 0813782106 | yes | Codetext | m² | Trockenbauarbeiten | Wand | Innenwand 1-Schalig | WI-LB | 0 | A | 3.75 | 1163HWa0812442199 | NEW | no | no | REI 60-A1 - D,s2-d0 /A1 | 0 | no | 47 | no | Codetext | AllplanAttributes - Positionsnummer_Text: U100
 | H2 Ebene +1 | WI-HW 60 | 1163Wa 0814592202 | yes | Codetext | m² | Zimmer- und Holzbauarbeiten | Wand | Innenwand 1-Schalig | WI-HW 60 | 0 | A | 3.75 | 1163HWa0812794796 | NEW | no | no | REI 60-A1 - D,s2-d0 +A1 | 0 | no | 47 | no | Codetext | AllplanAttributes - ash W_laufende Nr. Statik: 1 (W 1.0/ 1.1/ 1.2); Positionsnummer_Text: U100
 | H2 Ebene +1 | WI-PR | 1163Wa 0812836366 | yes | Codetext | m² | Trockenbauarbeiten | Wand | "BS-Beplankung; 2-fach Gipsfaserplatten" | WI-PR | 0 | A | 3.75 | 1163HWa0812836365 | NEW |  | no |  | 0 | no | 0 | no | Codetext | AllplanAttributes - Positionsnummer_Text: U100
 | H2 Ebene +1 | WI-PR | 1163Wa 0812836393 | yes | Codetext | m² | Trockenbauarbeiten | Wand | "BS-Beplankung; 2-fach Gipsfaserplatten" | WI-PR | 0 | A | 3.75 | 1163HWa0812836365 | NEW |  | no |  | 0 | no | 0 | no | Codetext | AllplanAttributes - Positionsnummer_Text: U100
 | H2 Ebene +1 | WI-PR | 1163Wa 0814593587 | yes | Codetext | m² | Trockenbauarbeiten | Wand | "BS-Beplankung; 2-fach Gipsfaserplatten" | WI-PR | 0 | A | 3.75 | 1163HWa0812836365 | NEW |  | no |  | 0 | no | 0 | no | Codetext | AllplanAttributes - Positionsnummer_Text: U100
 | H2 Ebene +1 | WI-PR | 1163Wa 0814593601 | yes | Codetext | m² | Trockenbauarbeiten | Wand | "BS-Beplankung; 2-fach Gipsfaserplatten" | WI-PR | 0 | A | 3.75 | 1163HWa0812836365 | NEW |  | no |  | 0 | no | 0 | no | Codetext | AllplanAttributes - Positionsnummer_Text: U100
 | H2 Ebene +1 | WI-LB | 1163Wa 0814593643 | yes | Codetext | m² | Trockenbauarbeiten | Wand | Innenwand 1-Schalig | WI-LB | 0 | A | 3.75 | 1163HWa0812428824 | NEW |  | no | 0 | 0 | no |  | no | Codetext | AllplanAttributes - W_Deckenanschluss: Gleitender Deckenanschluss Fall 01; ash_W_Trockenbau_Qualitäten: 18; Positionsnummer_Text: U100
 | H2 Ebene +1 | WI-LB | 1163Wa 0814593654 | yes | Codetext | m² | Trockenbauarbeiten | Wand | Innenwand 1-Schalig | WI-LB | 0 | A | 3.75 | 1163HWa0812428824 | NEW |  | no | 0 | 0 | no |  | no | Codetext | AllplanAttributes - W_Deckenanschluss: Gleitender Deckenanschluss Fall 01; ash_W_Trockenbau_Qualitäten: 18; Positionsnummer_Text: U100
 | H2 Ebene +1 | WI-LB | 1163Wa 0814593666 | yes | Codetext | m² | Trockenbauarbeiten | Wand | Innenwand 1-Schalig | WI-LB | 0 | A | 3.75 | 1163HWa0812428824 | NEW |  | no | 0 | 0 | no |  | no | Codetext | AllplanAttributes - W_Deckenanschluss: Gleitender Deckenanschluss Fall 01; ash_W_Trockenbau_Qualitäten: 18; Positionsnummer_Text: U100
 | H2 Ebene +1 | WI-LB | 1163Wa 0814593678 | yes | Codetext | m² | Trockenbauarbeiten | Wand | Innenwand 1-Schalig | WI-LB | 0 | A | 3.75 | 1163HWa0812428824 | NEW |  | no | 0 | 0 | no |  | no | Codetext | AllplanAttributes - W_Deckenanschluss: Gleitender Deckenanschluss Fall 01; Positionsnummer_Text: U100
 | H2 Ebene +1 | WI-LB | 1163Wa 0814593632 | yes | Codetext | m² | Trockenbauarbeiten | Wand | Innenwand 1-Schalig | WI-LB | 0 | A | 3.75 | 1163HWa0812428824 | NEW |  | no | 0 | 0 | no |  | no | Codetext | AllplanAttributes - W_Deckenanschluss: Gleitender Deckenanschluss Fall 01; ash_W_Trockenbau_Qualitäten: 18; Positionsnummer_Text: U100
 | H2 Ebene +1 | WI-LB | 1163Wa 0814593748 | yes | Codetext | m² | Trockenbauarbeiten | Wand | Innenwand 1-Schalig | WI-LB | 0 | A | 3.75 | 1163HWa0812428824 | NEW |  | no | 0 | 0 | no |  | no | Codetext | AllplanAttributes - W_Deckenanschluss: Gleitender Deckenanschluss Fall 01; Positionsnummer_Text: U100
 | H2 Ebene +1 | WI-LB | 1163Wa 0814593754 | yes | Codetext | m² | Trockenbauarbeiten | Wand | Innenwand 1-Schalig | WI-LB | 0 | A | 3.75 | 1163HWa0812428824 | NEW |  | no | 0 | 0 | no |  | no | Codetext | AllplanAttributes - W_Deckenanschluss: Gleitender Deckenanschluss Fall 01; Positionsnummer_Text: U100
 | H2 Ebene +1 | WI-PR | 1163Wa 0812836451 | yes | Codetext | m² | Trockenbauarbeiten | Wand | "BS-Beplankung; 2-fach Gipsfaserplatten" | WI-PR | 0 | A | 3.75 | 1163HWa0812836365 | NEW |  | no |  | 0 | no | 0 | no | Codetext | AllplanAttributes - Positionsnummer_Text: U100
 | H2 Ebene +1 | WI-PR | 1163Wa 0812836436 | yes | Codetext | m² | Trockenbauarbeiten | Wand | "BS-Beplankung; 2-fach Gipsfaserplatten" | WI-PR | 0 | A | 3.75 | 1163HWa0812836365 | NEW |  | no |  | 0 | no | 0 | no | Codetext | AllplanAttributes - Positionsnummer_Text: U100
 | H2 Ebene +1 | WI-PR | 1163Wa 0812836463 | yes | Codetext | m² | Trockenbauarbeiten | Wand | "BS-Beplankung; 2-fach Gipsfaserplatten" | WI-PR | 0 | A | 3.75 | 1163HWa0812836365 | NEW |  | no |  | 0 | no | 0 | no | Codetext | AllplanAttributes - Positionsnummer_Text: U100
 | H2 Ebene +1 | WI-PR | 1163Wa 0812836441 | yes | Codetext | m² | Trockenbauarbeiten | Wand | "BS-Beplankung; 2-fach Gipsfaserplatten" | WI-PR | 0 | A | 3.75 | 1163HWa0812836365 | NEW |  | no |  | 0 | no | 0 | no | Codetext | AllplanAttributes - Positionsnummer_Text: U100
 | H2 Ebene +1 | WI-LB | 1163Wa 0814593879 | yes | Codetext | m² | Trockenbauarbeiten | Wand | Innenwand 1-Schalig | WI-LB | 0 | A | 3.75 | 1163HWa0812428824 | NEW |  | no | 0 | 0 | no |  | no | Codetext | AllplanAttributes - W_Deckenanschluss: Gleitender Deckenanschluss Fall 01; Positionsnummer_Text: U100
 | H2 Ebene +1 | WI-LB | 1163Wa 0814593886 | yes | Codetext | m² | Trockenbauarbeiten | Wand | Innenwand 1-Schalig | WI-LB | 0 | A | 3.75 | 1163HWa0812428824 | NEW |  | no | 0 | 0 | no |  | no | Codetext | AllplanAttributes - W_Deckenanschluss: Gleitender Deckenanschluss Fall 01; Positionsnummer_Text: U100
 | H2 Ebene +1 | WI-LB | 1163Wa 0814594577 | yes | Codetext | m² | Trockenbauarbeiten | Wand | Innenwand 1-Schalig | WI-LB | 0 | A | 3.75 | 1163HWa0813714397 | NEW |  | no | 0 | 0 | no | 47 | no | Codetext | AllplanAttributes - W_Deckenanschluss: Gleitender Deckenanschluss Fall 01; ash_W_Trockenbau_Qualitäten: 1b; Positionsnummer_Text: U100
 | H2 Ebene +1 | WI-HW 60 | 1163Wa 0814594926 | yes | Codetext | m² | Zimmer- und Holzbauarbeiten | Wand | Innenwand 1-Schalig | WI-HW 60 | 0 | A | 3.75 | 1163HWa0812430886 | NEW |  | no | 0 | 0 | no | 47 | no | Codetext | AllplanAttributes - ash W_laufende Nr. Statik: 3 (W 3.0); Positionsnummer_Text: U100
 | H2 Ebene +1 | WI-VS | 1163Wa 0813672369 | yes | Codetext | m² | Trockenbauarbeiten | Wand | Installationswand | WI-VS | 0 | A | 3.75 | 1163HWa0813672368 | NEW |  | no | 0 | 0 | no | 0 | no | Codetext | AllplanAttributes - W_Deckenanschluss: Gleitender Deckenanschluss Fall 01; ash_W_Trockenbau_Qualitäten: 18; Positionsnummer_Text: U100
 | H2 Ebene +1 | WI-LB | 1163Wa 0812447118 | yes | Codetext | m² | Trockenbauarbeiten | Wand | Innenwand 1-Schalig | WI-LB | 0 | A | 3.75 | 1163HWa0812430571 | NEW | no | no | REI 60-A1 - D,s2-d0 /A1 | 0 | no | 52 | no | Codetext | AllplanAttributes - ash_W_Trockenbau_Qualitäten: 6; Positionsnummer_Text: U100
 | H2 Ebene +1 | Installationsraum | 1163Wa 0813782841 | yes | Codetext | m² | Trockenbauarbeiten | Wand | Innenwand 1-Schalig | Installationsraum | 0 | A | 3.75 | 1163HWa0812430571 | NEW | no | no | 0 | 0 | no | 52 | no | Codetext | AllplanAttributes - Positionsnummer_Text: U100
 | H2 Ebene +1 | WI-HW 60 | 1163Wa 0813782842 | yes | Codetext | m² | Zimmer- und Holzbauarbeiten | Wand | Innenwand 1-Schalig | WI-HW 60 | 0 | A | 3.75 | 1163HWa0812430571 | NEW | no | no | REI 60-A1 - D,s2-d0 +A1 | 0 | no | 52 | no | Codetext | AllplanAttributes - ash W_laufende Nr. Statik: 3 (W 3.0); Positionsnummer_Text: U100
 | H2 Ebene +1 | WI-IW | 1163Wa 0812464273 | yes | Codetext | m² | Trockenbauarbeiten | Wand | Installationswand | WI-IW | 0 | A | 3.75 | 1163HWa0812464272 | NEW |  | no | 0 | 0 | no | 0 | no | Codetext | AllplanAttributes - W_Deckenanschluss: Gleitender Deckenanschluss Fall 01; ash_W_Trockenbau_Qualitäten: 18; Positionsnummer_Text: U100
 | H2 Ebene +1 | WI-PR | 1163Wa 0814596038 | yes | Codetext | m² | Trockenbauarbeiten | Wand | "BS-Beplankung; 2-fach Gipsfaserplatten" | WI-PR | 0 | A | 3.75 | 1163HWa0812836365 | NEW |  | no |  | 0 | no | 0 | no | Codetext | AllplanAttributes - Positionsnummer_Text: U100
 | H2 Ebene +1 | WI-PR | 1163Wa 0814596034 | yes | Codetext | m² | Trockenbauarbeiten | Wand | "BS-Beplankung; 2-fach Gipsfaserplatten" | WI-PR | 0 | A | 3.75 | 1163HWa0812836365 | NEW |  | no |  | 0 | no | 0 | no | Codetext | AllplanAttributes - Positionsnummer_Text: U100
 | H2 Ebene +1 | WI-PR | 1163Wa 0814596032 | yes | Codetext | m² | Trockenbauarbeiten | Wand | "BS-Beplankung; 2-fach Gipsfaserplatten" | WI-PR | 0 | A | 3.75 | 1163HWa0812836365 | NEW |  | no |  | 0 | no | 0 | no | Codetext | AllplanAttributes - Positionsnummer_Text: U100
 | H2 Ebene +1 | WI-PR | 1163Wa 0814596036 | yes | Codetext | m² | Trockenbauarbeiten | Wand | "BS-Beplankung; 2-fach Gipsfaserplatten" | WI-PR | 0 | A | 3.75 | 1163HWa0812836365 | NEW |  | no |  | 0 | no | 0 | no | Codetext | AllplanAttributes - Positionsnummer_Text: U100
 | H2 Ebene +1 | WI-LB | 1163Wa 0814596118 | yes | Codetext | m² | Trockenbauarbeiten | Wand | Innenwand 1-Schalig | WI-LB | 0 | A | 3.75 | 1163HWa0812434677 | NEW |  | no | 0 | 0 | no | 52 | no | Codetext | AllplanAttributes - Sicherheitsklasse: -; Positionsnummer_Text: U100
 | H2 Ebene +1 | WI-PR | 1163Wa 0814596831 | yes | Codetext | m² | Trockenbauarbeiten | Wand | "BS-Beplankung; 2-fach Gipsfaserplatten" | WI-PR | 0 | A | 3.75 | 1163HWa0812836365 | NEW |  | no |  | 0 | no | 0 | no | Codetext | AllplanAttributes - Positionsnummer_Text: U100
 | H2 Ebene +1 | WI-PR | 1163Wa 0814596833 | yes | Codetext | m² | Trockenbauarbeiten | Wand | "BS-Beplankung; 2-fach Gipsfaserplatten" | WI-PR | 0 | A | 3.75 | 1163HWa0812836365 | NEW |  | no |  | 0 | no | 0 | no | Codetext | AllplanAttributes - Positionsnummer_Text: U100
 | H2 Ebene +1 | WI-PR | 1163Wa 0814596835 | yes | Codetext | m² | Trockenbauarbeiten | Wand | "BS-Beplankung; 2-fach Gipsfaserplatten" | WI-PR | 0 | A | 3.75 | 1163HWa0812836365 | NEW |  | no |  | 0 | no | 0 | no | Codetext | AllplanAttributes - Positionsnummer_Text: U100
 | H2 Ebene +1 | WI-PR | 1163Wa 0814596829 | yes | Codetext | m² | Trockenbauarbeiten | Wand | "BS-Beplankung; 2-fach Gipsfaserplatten" | WI-PR | 0 | A | 3.75 | 1163HWa0812836365 | NEW |  | no |  | 0 | no | 0 | no | Codetext | AllplanAttributes - Positionsnummer_Text: U100
 | H2 Ebene +1 | WI-LB | 1163Wa 0812520562 | yes | Codetext | m² | Trockenbauarbeiten | Wand | Innenwand 1-Schalig | WI-LB | 0 | A | 3.75 | 1163HWa0812520561 | NEW | no | no | REI 60-A1 - D,s2-d0 /A1 | 0 | no | 52 | no | Codetext | AllplanAttributes - ash_W_Trockenbau_Qualitäten: 6; Positionsnummer_Text: U100
 | H2 Ebene +1 | WI-HW 60 | 1163Wa 0813785438 | yes | Codetext | m² | Zimmer- und Holzbauarbeiten | Wand | Innenwand 1-Schalig | WI-HW 60 | 0 | A | 3.75 | 1163HWa0812520561 | NEW | yes | no | REI 60-A1 - D,s2-d0 +A1 | 0 | no | 52 | no | Codetext | AllplanAttributes - ash W_laufende Nr. Statik: 3 (W 3.0); Positionsnummer_Text: U100
 | H2 Ebene +1 | WI-HW 60 | 1163Wa 0814611511 | yes | Codetext | m² | Zimmer- und Holzbauarbeiten | Wand | Innenwand 1-Schalig | WI-HW 60 | 0 | A | 3.75 | 1163HWa0812520561 | NEW |  | no | REI 60-A1 - D,s2-d0 +A1 | 0 | no | 52 | no | Codetext | AllplanAttributes - ash W_laufende Nr. Statik: 3 (W 3.0); Positionsnummer_Text: U100
 | H2 Ebene +1 | WI-LB | 1163Wa 0814611700 | yes | Codetext | m² | Trockenbauarbeiten | Wand | Innenwand 1-Schalig | WI-LB | 0 | A | 3.75 | 1163HWa0812428824 | NEW |  | no | 0 | 0 | no |  | no | Codetext | AllplanAttributes - W_Deckenanschluss: Gleitender Deckenanschluss Fall 01; ash_W_Trockenbau_Qualitäten: 18; Positionsnummer_Text: U100
 | H2 Ebene +1 | WI-LB | 1163Wa 0814611725 | yes | Codetext | m² | Trockenbauarbeiten | Wand | Innenwand 1-Schalig | WI-LB | 0 | A | 3.75 | 1163HWa0812428824 | NEW |  | no | 0 | 0 | no |  | no | Codetext | AllplanAttributes - W_Deckenanschluss: Gleitender Deckenanschluss Fall 01; ash_W_Trockenbau_Qualitäten: 18; Positionsnummer_Text: U100
 | H2 Ebene +1 | WI-LB | 1163Wa 0814611736 | yes | Codetext | m² | Trockenbauarbeiten | Wand | Innenwand 1-Schalig | WI-LB | 0 | A | 3.75 | 1163HWa0812428824 | NEW |  | no | 0 | 0 | no |  | no | Codetext | AllplanAttributes - W_Deckenanschluss: Gleitender Deckenanschluss Fall 01; ash_W_Trockenbau_Qualitäten: 18; Positionsnummer_Text: U100
 | H2 Ebene +1 | WI-LB | 1163Wa 0814611757 | yes | Codetext | m² | Trockenbauarbeiten | Wand | Innenwand 1-Schalig | WI-LB | 0 | A | 3.75 | 1163HWa0812428824 | NEW |  | no | 0 | 0 | no |  | no | Codetext | AllplanAttributes - W_Deckenanschluss: Gleitender Deckenanschluss Fall 01; ash_W_Trockenbau_Qualitäten: 18; Positionsnummer_Text: U100
 | H2 Ebene +1 | WI-LB | 1163Wa 0814611765 | yes | Codetext | m² | Trockenbauarbeiten | Wand | Innenwand 1-Schalig | WI-LB | 0 | A | 3.75 | 1163HWa0812428824 | NEW |  | no | 0 | 0 | no |  | no | Codetext | AllplanAttributes - W_Deckenanschluss: Gleitender Deckenanschluss Fall 01; ash_W_Trockenbau_Qualitäten: 18; Positionsnummer_Text: U100
 | H2 Ebene +1 | WI-LB | 1163Wa 0814611853 | yes | Codetext | m² | Trockenbauarbeiten | Wand | Innenwand 1-Schalig | WI-LB | 0 | A | 3.75 | 1163HWa0812428824 | NEW |  | no | 0 | 0 | no |  | no | Codetext | AllplanAttributes - W_Deckenanschluss: Gleitender Deckenanschluss Fall 01; Positionsnummer_Text: U100
 | H2 Ebene +1 | WI-LB | 1163Wa 0814611787 | yes | Codetext | m² | Trockenbauarbeiten | Wand | Innenwand 1-Schalig | WI-LB | 0 | A | 3.75 | 1163HWa0812428824 | NEW |  | no | 0 | 0 | no |  | no | Codetext | AllplanAttributes - W_Deckenanschluss: Gleitender Deckenanschluss Fall 01; Positionsnummer_Text: U100
 | H2 Ebene +1 | WI-LB | 1163Wa 0814611844 | yes | Codetext | m² | Trockenbauarbeiten | Wand | Innenwand 1-Schalig | WI-LB | 0 | A | 3.75 | 1163HWa0812428824 | NEW |  | no | 0 | 0 | no |  | no | Codetext | AllplanAttributes - W_Deckenanschluss: Gleitender Deckenanschluss Fall 01; Positionsnummer_Text: U100
 | H2 Ebene +1 | WI-LB | 1163Wa 0814611865 | yes | Codetext | m² | Trockenbauarbeiten | Wand | Innenwand 1-Schalig | WI-LB | 0 | A | 3.75 | 1163HWa0812428824 | NEW |  | no | 0 | 0 | no |  | no | Codetext | AllplanAttributes - W_Deckenanschluss: Gleitender Deckenanschluss Fall 01; Positionsnummer_Text: U100
 | H2 Ebene +1 | WI-LB | 1163Wa 0814612238 | yes | Codetext | m² | Trockenbauarbeiten | Wand | Innenwand 1-Schalig | WI-LB | 0 | A | 3.75 | 1163HWa0812428824 | NEW |  | no | 0 | 0 | no |  | no | Codetext | AllplanAttributes - W_Deckenanschluss: Gleitender Deckenanschluss Fall 01; Positionsnummer_Text: U100
 | H2 Ebene +1 | WI-LB | 1163Wa 0814612237 | yes | Codetext | m² | Trockenbauarbeiten | Wand | Innenwand 1-Schalig | WI-LB | 0 | A | 3.75 | 1163HWa0812428824 | NEW |  | no | 0 | 0 | no |  | no | Codetext | AllplanAttributes - W_Deckenanschluss: Gleitender Deckenanschluss Fall 01; Positionsnummer_Text: U100
 | H2 Ebene +1 | WI-LB | 1163Wa 0814612241 | yes | Codetext | m² | Trockenbauarbeiten | Wand | Innenwand 1-Schalig | WI-LB | 0 | A | 3.75 | 1163HWa0812428824 | NEW |  | no | 0 | 0 | no |  | no | Codetext | AllplanAttributes - W_Deckenanschluss: Gleitender Deckenanschluss Fall 01; Positionsnummer_Text: U100
 | H2 Ebene +1 | WI-LB | 1163Wa 0814612242 | yes | Codetext | m² | Trockenbauarbeiten | Wand | Innenwand 1-Schalig | WI-LB | 0 | A | 3.75 | 1163HWa0812428824 | NEW |  | no | 0 | 0 | no |  | no | Codetext | AllplanAttributes - W_Deckenanschluss: Gleitender Deckenanschluss Fall 01; Positionsnummer_Text: U100
 | H2 Ebene +1 | WI-LB | 1163Wa 0814612240 | yes | Codetext | m² | Trockenbauarbeiten | Wand | Innenwand 1-Schalig | WI-LB | 0 | A | 3.75 | 1163HWa0812428824 | NEW |  | no | 0 | 0 | no |  | no | Codetext | AllplanAttributes - W_Deckenanschluss: Gleitender Deckenanschluss Fall 01; ash_W_Trockenbau_Qualitäten: 18; Positionsnummer_Text: U100
 | H2 Ebene +1 | WI-LB | 1163Wa 0814612239 | yes | Codetext | m² | Trockenbauarbeiten | Wand | Innenwand 1-Schalig | WI-LB | 0 | A | 3.75 | 1163HWa0812428824 | NEW |  | no | 0 | 0 | no |  | no | Codetext | AllplanAttributes - W_Deckenanschluss: Gleitender Deckenanschluss Fall 01; ash_W_Trockenbau_Qualitäten: 18; Positionsnummer_Text: U100
 | H2 Ebene +1 | WI-LB | 1163Wa 0814613343 | yes | Codetext | m² | Trockenbauarbeiten | Wand | Innenwand 1-Schalig | WI-LB | 0 | A | 3.75 | 1163HWa0813714673 | NEW | no | no | 0 | 0 | no | 47 | no | Codetext | AllplanAttributes - W_Deckenanschluss: Gleitender Deckenanschluss Fall 01; ash_W_Trockenbau_Qualitäten: 1b; Positionsnummer_Text: U100
 | H2 Ebene +1 | WI-LB | 1163Wa 0814613362 | yes | Codetext | m² | Trockenbauarbeiten | Wand | Innenwand 1-Schalig | WI-LB | 0 | A | 3.75 | 1163HWa0813714397 | NEW | no | no | 0 | 0 | no | 0 | no | Codetext | AllplanAttributes - W_Deckenanschluss: Gleitender Deckenanschluss Fall 01; ash_W_Trockenbau_Qualitäten: 18; Positionsnummer_Text: U100
 | H2 Ebene +1 | WI-LB | 1163Wa 0814613367 | yes | Codetext | m² | Trockenbauarbeiten | Wand | Innenwand 1-Schalig | WI-LB | 0 | A | 3.75 | 1163HWa0813714397 | NEW | no | no | 0 | 0 | no | 0 | no | Codetext | AllplanAttributes - W_Deckenanschluss: Gleitender Deckenanschluss Fall 01; ash_W_Trockenbau_Qualitäten: 18; Positionsnummer_Text: U100
 | H2 Ebene +1 | WI-LB | 1163Wa 0814613383 | yes | Codetext | m² | Trockenbauarbeiten | Wand | Innenwand 1-Schalig | WI-LB | 0 | A | 3.75 | 1163HWa0813714397 | NEW | no | no | 0 | 0 | no | 0 | no | Codetext | AllplanAttributes - W_Deckenanschluss: Gleitender Deckenanschluss Fall 01; ash_W_Trockenbau_Qualitäten: 18; Positionsnummer_Text: U100
 | H2 Ebene +1 | WI-LB | 1163Wa 0814613393 | yes | Codetext | m² | Trockenbauarbeiten | Wand | Innenwand 1-Schalig | WI-LB | 0 | A | 3.75 | 1163HWa0813714397 | NEW | no | no | 0 | 0 | no | 0 | no | Codetext | AllplanAttributes - W_Deckenanschluss: Gleitender Deckenanschluss Fall 01; ash_W_Trockenbau_Qualitäten: 18; Positionsnummer_Text: U100
 | H2 Ebene +1 | WI-LB | 1163Wa 0814613458 | yes | Codetext | m² | Trockenbauarbeiten | Wand | Innenwand 1-Schalig | WI-LB | 0 | A | 3.75 | 1163HWa0813714673 | NEW |  | no | 0 | 0 | no | 0 | no | Codetext | AllplanAttributes - W_Deckenanschluss: Gleitender Deckenanschluss Fall 01; ash_W_Trockenbau_Qualitäten: 18; Positionsnummer_Text: U100
 | H2 Ebene +1 | WI-LB | 1163Wa 0814613432 | yes | Codetext | m² | Trockenbauarbeiten | Wand | Innenwand 1-Schalig | WI-LB | 0 | A | 3.75 | 1163HWa0813714673 | NEW |  | no | 0 | 0 | no | 0 | no | Codetext | AllplanAttributes - W_Deckenanschluss: Gleitender Deckenanschluss Fall 01; ash_W_Trockenbau_Qualitäten: 18; Positionsnummer_Text: U100
 | H2 Ebene +1 | WI-LB | 1163Wa 0814613427 | yes | Codetext | m² | Trockenbauarbeiten | Wand | Innenwand 1-Schalig | WI-LB | 0 | A | 3.75 | 1163HWa0813714673 | NEW |  | no | 0 | 0 | no | 0 | no | Codetext | AllplanAttributes - W_Deckenanschluss: Gleitender Deckenanschluss Fall 01; ash_W_Trockenbau_Qualitäten: 18; Positionsnummer_Text: U100
 | H2 Ebene +1 | WI-LB | 1163Wa 0814613448 | yes | Codetext | m² | Trockenbauarbeiten | Wand | Innenwand 1-Schalig | WI-LB | 0 | A | 3.75 | 1163HWa0813714673 | NEW |  | no | 0 | 0 | no | 0 | no | Codetext | AllplanAttributes - W_Deckenanschluss: Gleitender Deckenanschluss Fall 01; ash_W_Trockenbau_Qualitäten: 18; Positionsnummer_Text: U100
 | H2 Ebene +1 | WI-PR | 1163Wa 0814614765 | yes | Codetext | m² | Trockenbauarbeiten | Wand | "BS-Beplankung; 2-fach Gipsfaserplatten" | WI-PR | 0 | A | 3.75 | 1163HWa0812836365 | NEW |  | no |  | 0 | no | 0 | no | Codetext | AllplanAttributes - Positionsnummer_Text: U100
 | H2 Ebene +1 | WI-PR | 1163Wa 0814614766 | yes | Codetext | m² | Trockenbauarbeiten | Wand | "BS-Beplankung; 2-fach Gipsfaserplatten" | WI-PR | 0 | A | 3.75 | 1163HWa0812836365 | NEW |  | no |  | 0 | no | 0 | no | Codetext | AllplanAttributes - Positionsnummer_Text: U100
 | H2 Ebene +1 | WI-PR | 1163Wa 0814614767 | yes | Codetext | m² | Trockenbauarbeiten | Wand | "BS-Beplankung; 2-fach Gipsfaserplatten" | WI-PR | 0 | A | 3.75 | 1163HWa0812836365 | NEW |  | no |  | 0 | no | 0 | no | Codetext | AllplanAttributes - Positionsnummer_Text: U100
 | H2 Ebene +1 | WI-PR | 1163Wa 0814614764 | yes | Codetext | m² | Trockenbauarbeiten | Wand | "BS-Beplankung; 2-fach Gipsfaserplatten" | WI-PR | 0 | A | 3.75 | 1163HWa0812836365 | NEW |  | no |  | 0 | no | 0 | no | Codetext | AllplanAttributes - Positionsnummer_Text: U100
 | H2 Ebene +1 | WI-PR | 1163Wa 0814614788 | yes | Codetext | m² | Trockenbauarbeiten | Wand | "BS-Beplankung; 2-fach Gipsfaserplatten" | WI-PR | 0 | A | 3.75 | 1163HWa0812836365 | NEW |  | no |  | 0 | no | 0 | no | Codetext | AllplanAttributes - Positionsnummer_Text: U100
 | H2 Ebene +1 | WI-PR | 1163Wa 0814614787 | yes | Codetext | m² | Trockenbauarbeiten | Wand | "BS-Beplankung; 2-fach Gipsfaserplatten" | WI-PR | 0 | A | 3.75 | 1163HWa0812836365 | NEW |  | no |  | 0 | no | 0 | no | Codetext | AllplanAttributes - Positionsnummer_Text: U100
 | H2 Ebene +1 | WI-PR | 1163Wa 0814614786 | yes | Codetext | m² | Trockenbauarbeiten | Wand | "BS-Beplankung; 2-fach Gipsfaserplatten" | WI-PR | 0 | A | 3.75 | 1163HWa0812836365 | NEW |  | no |  | 0 | no | 0 | no | Codetext | AllplanAttributes - Positionsnummer_Text: U100
 | H2 Ebene +1 | WI-PR | 1163Wa 0814614789 | yes | Codetext | m² | Trockenbauarbeiten | Wand | "BS-Beplankung; 2-fach Gipsfaserplatten" | WI-PR | 0 | A | 3.75 | 1163HWa0812836365 | NEW |  | no |  | 0 | no | 0 | no | Codetext | AllplanAttributes - Positionsnummer_Text: U100
 | H2 Ebene +1 | WI-HW 60 | 1163Wa 0814184392 | yes | Codetext | m² | Zimmer- und Holzbauarbeiten | Wand | Innenwand 1-Schalig | WI-HW 60 | 0 | A | 3.75 | 1163HWa0812438661 | NEW | no | no | 0 | 0 | no |  | no | Codetext | AllplanAttributes - Sicherheitsklasse: -; Positionsnummer_Text: U100
 | H2 Ebene +1 | WI-PR | 1163Wa 0814615194 | yes | Codetext | m² | Trockenbauarbeiten | Wand | "BS-Beplankung; 2-fach Gipsfaserplatten" | WI-PR | 0 | A | 3.75 | 1163HWa0812836365 | NEW |  | no |  | 0 | no | 0 | no | Codetext | AllplanAttributes - Positionsnummer_Text: U100
 | H2 Ebene +1 | WI-PR | 1163Wa 0814615193 | yes | Codetext | m² | Trockenbauarbeiten | Wand | "BS-Beplankung; 2-fach Gipsfaserplatten" | WI-PR | 0 | A | 3.75 | 1163HWa0812836365 | NEW |  | no |  | 0 | no | 0 | no | Codetext | AllplanAttributes - Positionsnummer_Text: U100
 | H2 Ebene +1 | WI-PR | 1163Wa 0814615192 | yes | Codetext | m² | Trockenbauarbeiten | Wand | "BS-Beplankung; 2-fach Gipsfaserplatten" | WI-PR | 0 | A | 3.75 | 1163HWa0812836365 | NEW |  | no |  | 0 | no | 0 | no | Codetext | AllplanAttributes - Positionsnummer_Text: U100
 | H2 Ebene +1 | WI-PR | 1163Wa 0814615195 | yes | Codetext | m² | Trockenbauarbeiten | Wand | "BS-Beplankung; 2-fach Gipsfaserplatten" | WI-PR | 0 | A | 3.75 | 1163HWa0812836365 | NEW |  | no |  | 0 | no | 0 | no | Codetext | AllplanAttributes - Positionsnummer_Text: U100
 | H2 Ebene +1 | WI-PR | 1163Wa 0814615215 | yes | Codetext | m² | Trockenbauarbeiten | Wand | "BS-Beplankung; 2-fach Gipsfaserplatten" | WI-PR | 0 | A | 3.75 | 1163HWa0812836365 | NEW |  | no |  | 0 | no | 0 | no | Codetext | AllplanAttributes - Positionsnummer_Text: U100
 | H2 Ebene +1 | WI-PR | 1163Wa 0814615216 | yes | Codetext | m² | Trockenbauarbeiten | Wand | "BS-Beplankung; 2-fach Gipsfaserplatten" | WI-PR | 0 | A | 3.75 | 1163HWa0812836365 | NEW |  | no |  | 0 | no | 0 | no | Codetext | AllplanAttributes - Positionsnummer_Text: U100
 | H2 Ebene +1 | WI-PR | 1163Wa 0814615217 | yes | Codetext | m² | Trockenbauarbeiten | Wand | "BS-Beplankung; 2-fach Gipsfaserplatten" | WI-PR | 0 | A | 3.75 | 1163HWa0812836365 | NEW |  | no |  | 0 | no | 0 | no | Codetext | AllplanAttributes - Positionsnummer_Text: U100
 | H2 Ebene +1 | WI-PR | 1163Wa 0814615214 | yes | Codetext | m² | Trockenbauarbeiten | Wand | "BS-Beplankung; 2-fach Gipsfaserplatten" | WI-PR | 0 | A | 3.75 | 1163HWa0812836365 | NEW |  | no |  | 0 | no | 0 | no | Codetext | AllplanAttributes - Positionsnummer_Text: U100
Promat / BS | H2 Ebene +1 | WI-PR | 1163Wa 0814615335 | yes | Codetext | m² | Trockenbauarbeiten | Wand | Promat / BS | WI-PR | 0 | A | 3.75 | 1163HWa0812835805 | NEW | no | no |  | 0 | no | 0 | no | Codetext | AllplanAttributes - Positionsnummer_Text: U100
Promat / BS | H2 Ebene +1 | WI-PR | 1163Wa 0814615347 | yes | Codetext | m² | Trockenbauarbeiten | Wand | Promat / BS | WI-PR | 0 | A | 3.75 | 1163HWa0812835805 | NEW | no | no |  | 0 | no | 0 | no | Codetext | AllplanAttributes - Positionsnummer_Text: U100
 | H2 Ebene +1 | WI-LB | 1163Wa 0812439875 | yes | Codetext | m² | Trockenbauarbeiten | Wand | Innenwand 1-Schalig | WI-LB | 0 | A | 3.75 | 1163HWa0812438517 | NEW |  | no | 0 | 0 | no | 47 | no | Codetext | AllplanAttributes - W_Deckenanschluss: Gleitender Deckenanschluss Fall 01; ash_W_Trockenbau_Qualitäten: 1e; Positionsnummer_Text: U100
 | H2 Ebene +1 | WI-LB | 1163Wa 0812524524 | yes | Codetext | m² | Trockenbauarbeiten | Wand | Innenwand 1-Schalig | WI-LB | 0 | A | 3.75 | 1163HWa0812524516 | NEW |  | no | 0 | 0 | no | 47 | no | Codetext | AllplanAttributes - W_Deckenanschluss: Gleitender Deckenanschluss Fall 01; ash_W_Trockenbau_Qualitäten: 1e; Positionsnummer_Text: U100
 | H2 Ebene +1 | WI-HW 60 | 1163Wa 0812488027 | yes | Codetext | m² | Zimmer- und Holzbauarbeiten | Wand | Innenwand 1-Schalig | WI-HW 60 | 0 | A | 3.75 | 1163HWa0812488025 | NEW | no | no | REI 60-A1 - D,s2-d0 +A1 | 0 | no | 47 | no | Codetext | AllplanAttributes - ash W_laufende Nr. Statik: 3 (W 3.0); Positionsnummer_Text: U100
 | H2 Ebene +1 | Installationsraum | 1163Wa 0813788825 | yes | Codetext | m² | Trockenbauarbeiten | Wand | Innenwand 1-Schalig | Installationsraum | 0 | A | 3.75 | 1163HWa0812488025 | NEW | no | no | 0 | 0 | no | 0 | no | Codetext | AllplanAttributes - Positionsnummer_Text: U100
 | H2 Ebene +1 | WI-LB | 1163Wa 0814103193 | yes | Codetext | m² | Trockenbauarbeiten | Wand | Innenwand 1-Schalig | WI-LB | 0 | A | 3.75 | 1163HWa0812488025 | NEW | no | no | REI 60-A1 - D,s2-d0 /A1 | 0 | no | 47 | no | Codetext | AllplanAttributes - ash_W_Trockenbau_Qualitäten: 8; Positionsnummer_Text: U100
 | H2 Ebene +1 | WI-HW 60 | 1163Wa 0814592283 | yes | Codetext | m² | Zimmer- und Holzbauarbeiten | Wand | Innenwand 1-Schalig | WI-HW 60 | 0 | A | 3.75 | 1163HWa0812794796 | NEW | no | no | REI 60-A1 - D,s2-d0 +A1 | 0 | no | 47 | no | Codetext | AllplanAttributes - ash W_laufende Nr. Statik: 1 (W 1.0/ 1.1/ 1.2); Positionsnummer_Text: U100
 | H2 Ebene +1 | WI-LB | 1163Wa 0814619184 | yes | Codetext | m² | Trockenbauarbeiten | Wand | Innenwand 1-Schalig | WI-LB | 0 | A | 3.75 | 1163HWa0812428611 | NEW | no | no | 0 | 0 | no | 0 | no | Codetext | AllplanAttributes - W_Deckenanschluss: Gleitender Deckenanschluss Fall 01; ash_W_Trockenbau_Qualitäten: 1; Positionsnummer_Text: U100
 | H2 Ebene +1 | WI-LB | 1163Wa 0814484845 | yes | Codetext | m² | Trockenbauarbeiten | Wand | Innenwand 1-Schalig | WI-LB | 0 | A | 3.75 | 1163HWa0812428611 | NEW | no | no | 0 | 0 | no | 0 | no | Codetext | AllplanAttributes - W_Deckenanschluss: Gleitender Deckenanschluss Fall 01; ash_W_Trockenbau_Qualitäten: 1a; Positionsnummer_Text: U100
 | H2 Ebene +1 | WI-VS | 1163Wa 0813671765 | yes | Codetext | m² | Trockenbauarbeiten | Wand | Installationswand | WI-VS | 0 | A | 3.75 | 1163HWa0813671764 | NEW |  | no | 0 | 0 | no | 0 | no | Codetext | AllplanAttributes - W_Deckenanschluss: Gleitender Deckenanschluss Fall 01; ash_W_Trockenbau_Qualitäten: 18; Positionsnummer_Text: U100
 | H2 Ebene +1 | WI-LB | 1163Wa 0812437627 | yes | Codetext | m² | Trockenbauarbeiten | Wand | Innenwand 1-Schalig | WI-LB | 0 | A | 3.75 | 1163HWa0812430763 | NEW |  | no | REI 30-A1 - D,s2-d0 +A1 | 0 | no | 0 | no | Codetext | AllplanAttributes - W_Deckenanschluss: Gleitender Deckenanschluss Fall 01; ash_W_Trockenbau_Qualitäten: 16; Positionsnummer_Text: U100
 | H2 Ebene +1 | WI-HW 60 | 1163Wa 0813790835 | yes | Codetext | m² | Zimmer- und Holzbauarbeiten | Wand | Innenwand 1-Schalig | WI-HW 60 | 0 | A | 3.75 | 1163HWa0812430763 | NEW |  | no | REI 30-A1 - D,s2-d0 +A1 | 0 | no | 0 | no | Codetext | AllplanAttributes - ash W_laufende Nr. Statik: 3 (W 3.0); Positionsnummer_Text: U100
 | H2 Ebene +1 | WI-LB | 1163Wa 0814620414 | yes | Codetext | m² | Trockenbauarbeiten | Wand | Innenwand 1-Schalig | WI-LB | 0 | A | 3.75 | 1163HWa0812430763 | NEW |  | no | REI 30-A1 - D,s2-d0 +A1 | 0 | no | 0 | no | Codetext | AllplanAttributes - W_Deckenanschluss: Gleitender Deckenanschluss Fall 01; ash_W_Trockenbau_Qualitäten: 16; Positionsnummer_Text: U100
 | H2 Ebene +1 | WI-HW 60 | 1163Wa 0814620412 | yes | Codetext | m² | Zimmer- und Holzbauarbeiten | Wand | Innenwand 1-Schalig | WI-HW 60 | 0 | A | 3.75 | 1163HWa0812430763 | NEW |  | no | REI 30-A1 - D,s2-d0 +A1 | 0 | no | 0 | no | Codetext | AllplanAttributes - ash W_laufende Nr. Statik: 3 (W 3.0); Positionsnummer_Text: U100
 | H2 Ebene +1 | WI-HW 60 | 1163Wa 0812440265 | yes | Codetext | m² | Zimmer- und Holzbauarbeiten | Wand | Innenwand 1-Schalig | WI-HW 60 | 0 | A | 3.75 | 1163HWa0812438820 | NEW | no | no | REI 60-A1 - D,s2-d0 +A1 | 0 | no | 47 | no | Codetext | AllplanAttributes - ash W_laufende Nr. Statik: 1 (W 1.0/ 1.1/ 1.2); Positionsnummer_Text: U100
 | H2 Ebene +1 | WI-LB | 1163Wa 0812439886 | yes | Codetext | m² | Trockenbauarbeiten | Wand | Innenwand 1-Schalig | WI-LB | 0 | A | 3.75 | 1163HWa0812438082 | NEW | no | no | REI 60-A1 - D,s2-d0 /A1 | 0 | no | 47 | no | Codetext | AllplanAttributes - ash_W_Trockenbau_Qualitäten: 6; Positionsnummer_Text: U100
 | H2 Ebene +1 | WI-HW 60 | 1163Wa 0813789131 | yes | Codetext | m² | Zimmer- und Holzbauarbeiten | Wand | Innenwand 1-Schalig | WI-HW 60 | 0 | A | 3.75 | 1163HWa0812438082 | NEW | yes | no | REI 60-A1 - D,s2-d0 +A1 | 0 | no | 47 | no | Codetext | AllplanAttributes - ash W_laufende Nr. Statik: 3 (W 3.0); Positionsnummer_Text: U100
 | H2 Ebene +1 | WI-HW 60 | 1163Wa 0814631094 | yes | Codetext | m² | Zimmer- und Holzbauarbeiten | Wand | Innenwand 1-Schalig | WI-HW 60 | 0 | A | 3.75 | 1163HWa0812438082 | NEW |  | no | REI 60-A1 - D,s2-d0 +A1 | 0 | no | 47 | no | Codetext | AllplanAttributes - ash W_laufende Nr. Statik: 3 (W 3.0); Positionsnummer_Text: U100
 | H2 Ebene +1 | WI-HW 60 | 1163Wa 0814644863 | yes | Codetext | m² | Zimmer- und Holzbauarbeiten | Wand | Innenwand 1-Schalig | WI-HW 60 | 0 | A | 3.75 | 1163HWa0812438184 | NEW | yes | no | REI 60-A1 - D,s2-d0 +A1 | 0 | no | 47 | no | Codetext | AllplanAttributes - ash W_laufende Nr. Statik: 1 (W 1.0/ 1.1/ 1.2); Positionsnummer_Text: U100
 | H2 Ebene +1 | WI-LB | 1163Wa 0814644861 | yes | Codetext | m² | Trockenbauarbeiten | Wand | Innenwand 1-Schalig | WI-LB | 0 | A | 3.75 | 1163HWa0812438184 | NEW | no | no | REI 60-A1 - D,s2-d0 /A1 | 0 | no | 47 | no | Codetext | AllplanAttributes - Positionsnummer_Text: U100
 | H2 Ebene +1 | WI-HW 60 | 1163Wa 0812438228 | yes | Codetext | m² | Zimmer- und Holzbauarbeiten | Wand | Innenwand 1-Schalig | WI-HW 60 | 0 | A | 3.75 | 1163HWa0812432924 | NEW | no | no | REI 30 | 0 | no | 47 | no | Codetext | AllplanAttributes - ash W_laufende Nr. Statik: 1 (W 1.0/ 1.1/ 1.2); Positionsnummer_Text: U100
 | H2 Ebene +1 | WI-LB | 1163Wa 0813780674 | yes | Codetext | m² | Trockenbauarbeiten | Wand | Innenwand 1-Schalig | WI-LB | 0 | A | 3.75 | 1163HWa0812432924 | NEW | no | no | REI 30-A1 - D,s2-d0 +A1 | 0 | no | 47 | no | Codetext | AllplanAttributes - ash_W_Trockenbau_Qualitäten: 6; Sicherheitsklasse: -; Positionsnummer_Text: U100
 | H2 Ebene +1 | WI-HW 60 | 1163Wa 0814659997 | yes | Codetext | m² | Zimmer- und Holzbauarbeiten | Wand | Innenwand 1-Schalig | WI-HW 60 | 0 | A | 3.75 | 1163HWa0812432924 | NEW | no | no | REI 30 | 0 | no | 47 | no | Codetext | AllplanAttributes - ash W_laufende Nr. Statik: 1 (W 1.0/ 1.1/ 1.2); Positionsnummer_Text: U100
 | H2 Ebene +1 | WI-LB | 1163Wa 0814659995 | yes | Codetext | m² | Trockenbauarbeiten | Wand | Innenwand 1-Schalig | WI-LB | 0 | A | 3.75 | 1163HWa0812432924 | NEW | no | no | REI 30-A1 - D,s2-d0 +A1 | 0 | no | 47 | no | Codetext | AllplanAttributes - ash_W_Trockenbau_Qualitäten: 6; Sicherheitsklasse: -; Positionsnummer_Text: U100
 | H2 Ebene +1 | WI-HW 60 | 1163Wa 0814660802 | yes | Codetext | m² | Zimmer- und Holzbauarbeiten | Wand | Innenwand 1-Schalig | WI-HW 60 | 0 | A | 3.75 | 1163HWa0812432924 | NEW | no | no | REI 30 | 0 | no | 47 | no | Codetext | AllplanAttributes - ash W_laufende Nr. Statik: 1 (W 1.0/ 1.1/ 1.2); Positionsnummer_Text: U100
 | H2 Ebene +1 | WI-LB | 1163Wa 0814660801 | yes | Codetext | m² | Trockenbauarbeiten | Wand | Innenwand 1-Schalig | WI-LB | 0 | A | 3.75 | 1163HWa0812432924 | NEW | no | no | REI 30-A1 - D,s2-d0 +A1 | 0 | no | 47 | no | Codetext | AllplanAttributes - ash_W_Trockenbau_Qualitäten: 6; Sicherheitsklasse: -; Positionsnummer_Text: U100
 | H2 Ebene +1 | WI-HW 60 | 1163Wa 0814661303 | yes | Codetext | m² | Zimmer- und Holzbauarbeiten | Wand | Innenwand 1-Schalig | WI-HW 60 | 0 | A | 3.75 | 1163HWa0812432924 | NEW | no | no | REI 30 | 0 | no | 47 | no | Codetext | AllplanAttributes - ash W_laufende Nr. Statik: 1 (W 1.0/ 1.1/ 1.2); Positionsnummer_Text: U100
 | H2 Ebene +1 | WI-LB | 1163Wa 0814661302 | yes | Codetext | m² | Trockenbauarbeiten | Wand | Innenwand 1-Schalig | WI-LB | 0 | A | 3.75 | 1163HWa0812432924 | NEW | no | no | REI 30-A1 - D,s2-d0 +A1 | 0 | no | 47 | no | Codetext | AllplanAttributes - ash_W_Trockenbau_Qualitäten: 6; Sicherheitsklasse: -; Positionsnummer_Text: U100
 | H2 Ebene +1 | WI-HW 60 | 1163Wa 0814661357 | yes | Codetext | m² | Zimmer- und Holzbauarbeiten | Wand | Innenwand 1-Schalig | WI-HW 60 | 0 | A | 3.75 | 1163HWa0812438082 | NEW |  | no | REI 60-A1 - D,s2-d0 +A1 | 0 | no | 47 | no | Codetext | AllplanAttributes - ash W_laufende Nr. Statik: 3 (W 3.0); Positionsnummer_Text: U100
 | H2 Ebene +1 | WI-LB | 1163Wa 0812468455 |  | Codetext | m² | Trockenbauarbeiten | Wand |  |  | 0 | A | 3.75 | 1163HWa0812468442 | NEW | no | no | 0 | 0 | no | 0 | no | Codetext | AllplanAttributes - Ortscode_Geschoßbezeichnung: E01; W_Deckenanschluss: Gleitender Deckenanschluss Fall 03; ash_W_Trockenbau_Qualitäten: 10a; Positionsnummer_Text: U100
 | H2 Ebene +1 | WI-HW 60 | 1163Wa 0814661719 | yes | Codetext | m² | Zimmer- und Holzbauarbeiten | Wand | Innenwand 1-Schalig | WI-HW 60 | 0 | A | 3.75 | 1163HWa0812432924 | NEW |  | no | REI 30 | 0 | no | 47 | no | Codetext | AllplanAttributes - ash W_laufende Nr. Statik: 1 (W 1.0/ 1.1/ 1.2); Positionsnummer_Text: U100
 | H2 Ebene +1 | WI-HW 60 | 1163Wa 0814661734 | yes | Codetext | m² | Zimmer- und Holzbauarbeiten | Wand | Innenwand 1-Schalig | WI-HW 60 | 0 | A | 3.75 | 1163HWa0812432924 | NEW |  | no | REI 30 | 0 | no | 47 | no | Codetext | AllplanAttributes - ash W_laufende Nr. Statik: 1 (W 1.0/ 1.1/ 1.2); Positionsnummer_Text: U100
 | H2 Ebene +1 | WI-HW 60 | 1163Wa 0814661759 | yes | Codetext | m² | Zimmer- und Holzbauarbeiten | Wand | Innenwand 1-Schalig | WI-HW 60 | 0 | A | 3.75 | 1163HWa0812432924 | NEW |  | no | REI 30 | 0 | no | 47 | no | Codetext | AllplanAttributes - ash W_laufende Nr. Statik: 1 (W 1.0/ 1.1/ 1.2); Positionsnummer_Text: U100
 | H2 Ebene +1 | WI-LB | 1163Wa 0812847587 | yes | Codetext | m² | Trockenbauarbeiten | Wand | Innenwand 1-Schalig | WI-LB | 0 | A | 3.75 | 1163HWa0812847586 | NEW | no | no | REI 60-A1 - D,s2-d0 /A1 | 0 | no | 0 | no | Codetext | AllplanAttributes - Ortscode_Geschoßbezeichnung: E01; Positionsnummer_Text: U100
 | H2 Ebene +1 | WI-LB | 1163Wa 0814661904 | yes | Codetext | m² | Trockenbauarbeiten | Wand | Innenwand 1-Schalig | WI-LB | 0 | A | 3.75 | 1163HWa0812496570 | NEW |  | no | REI 30-A1 - D,s2-d0 +A1 | 0 | no | 47 | no | Codetext | AllplanAttributes - W_Deckenanschluss: Gleitender Deckenanschluss Fall 01; ash_W_Trockenbau_Qualitäten: 1b; Positionsnummer_Text: U100
 | H2 Ebene +1 | WI-LB | 1163Wa 0814661918 | yes | Codetext | m² | Trockenbauarbeiten | Wand | Innenwand 1-Schalig | WI-LB | 0 | A | 3.75 | 1163HWa0812496570 | NEW |  | no | REI 30-A1 - D,s2-d0 +A1 | 0 | no | 47 | no | Codetext | AllplanAttributes - W_Deckenanschluss: Gleitender Deckenanschluss Fall 01; ash_W_Trockenbau_Qualitäten: 1b; Positionsnummer_Text: U100
 | H2 Ebene +1 | WI-LB | 1163Wa 0814661928 | yes | Codetext | m² | Trockenbauarbeiten | Wand | Innenwand 1-Schalig | WI-LB | 0 | A | 3.75 | 1163HWa0812496570 | NEW |  | no | REI 30-A1 - D,s2-d0 +A1 | 0 | no | 47 | no | Codetext | AllplanAttributes - W_Deckenanschluss: Gleitender Deckenanschluss Fall 01; ash_W_Trockenbau_Qualitäten: 1b; Positionsnummer_Text: U100
 | H2 Ebene +1 | WI-LB | 1163Wa 0814661965 | yes | Codetext | m² | Trockenbauarbeiten | Wand | Innenwand 1-Schalig | WI-LB | 0 | A | 3.75 | 1163HWa0812438777 | NEW |  | no | 0 | 0 | no | 47 | no | Codetext | AllplanAttributes - W_Deckenanschluss: Gleitender Deckenanschluss Fall 01; Positionsnummer_Text: U100
 | H2 Ebene +1 | WI-HW 60 | 1163Wa 0814677217 | yes | Codetext | m² | Zimmer- und Holzbauarbeiten | Wand | Innenwand 1-Schalig | WI-HW 60 | 0 | A | 3.75 | 1163HWa0812425480 | NEW | no | no | REI 30 | 0 | no | 47 | no | Codetext | AllplanAttributes - ash W_laufende Nr. Statik: 1 (W 1.0/ 1.1/ 1.2); Positionsnummer_Text: U100
 | H2 Ebene +1 | WI-LB | 1163Wa 0814677215 | yes | Codetext | m² | Trockenbauarbeiten | Wand | Innenwand 1-Schalig | WI-LB | 0 | A | 3.75 | 1163HWa0812425480 | NEW | no | no | REI 30-A1 - D,s2-d0 +A1 | 0 | no | 47 | no | Codetext | AllplanAttributes - ash_W_Trockenbau_Qualitäten: 6; Sicherheitsklasse: -; Positionsnummer_Text: U100
 | H2 Ebene +1 | WI-HW 60 | 1163Wa 0814678299 | yes | Codetext | m² | Zimmer- und Holzbauarbeiten | Wand | Innenwand 1-Schalig | WI-HW 60 | 0 | A | 3.75 | 1163HWa0812425480 | NEW | no | no | REI 30 | 0 | no | 47 | no | Codetext | AllplanAttributes - ash W_laufende Nr. Statik: 1 (W 1.0/ 1.1/ 1.2); Positionsnummer_Text: U100
 | H2 Ebene +1 | WI-LB | 1163Wa 0814678298 | yes | Codetext | m² | Trockenbauarbeiten | Wand | Innenwand 1-Schalig | WI-LB | 0 | A | 3.75 | 1163HWa0812425480 | NEW | no | no | REI 30-A1 - D,s2-d0 +A1 | 0 | no | 47 | no | Codetext | AllplanAttributes - ash_W_Trockenbau_Qualitäten: 6; Sicherheitsklasse: -; Positionsnummer_Text: U100
 | H2 Ebene +1 | WI-HW 60 | 1163Wa 0812440280 | yes | Codetext | m² | Zimmer- und Holzbauarbeiten | Wand | Innenwand 1-Schalig | WI-HW 60 | 0 | A | 3.75 | 1163HWa0812425480 | NEW | no | no | REI 30 | 0 | no | 47 | no | Codetext | AllplanAttributes - ash W_laufende Nr. Statik: 1 (W 1.0/ 1.1/ 1.2); Positionsnummer_Text: U100
 | H2 Ebene +1 | WI-LB | 1163Wa 0813779695 | yes | Codetext | m² | Trockenbauarbeiten | Wand | Innenwand 1-Schalig | WI-LB | 0 | A | 3.75 | 1163HWa0812425480 | NEW | no | no | REI 30-A1 - D,s2-d0 +A1 | 0 | no | 47 | no | Codetext | AllplanAttributes - ash_W_Trockenbau_Qualitäten: 6; Sicherheitsklasse: -; Positionsnummer_Text: U100
 | H2 Ebene +1 | WI-HW 60 | 1163Wa 0814679130 | yes | Codetext | m² | Zimmer- und Holzbauarbeiten | Wand | Innenwand 1-Schalig | WI-HW 60 | 0 | A | 3.75 | 1163HWa0812425480 | NEW | no | no | REI 30 | 0 | no | 47 | no | Codetext | AllplanAttributes - ash W_laufende Nr. Statik: 1 (W 1.0/ 1.1/ 1.2); Positionsnummer_Text: U100
 | H2 Ebene +1 | WI-LB | 1163Wa 0814679129 | yes | Codetext | m² | Trockenbauarbeiten | Wand | Innenwand 1-Schalig | WI-LB | 0 | A | 3.75 | 1163HWa0812425480 | NEW | no | no | REI 30-A1 - D,s2-d0 +A1 | 0 | no | 47 | no | Codetext | AllplanAttributes - ash_W_Trockenbau_Qualitäten: 6; Sicherheitsklasse: -; Positionsnummer_Text: U100
 | H2 Ebene +1 | WI-HW 60 | 1163Wa 0814679204 | yes | Codetext | m² | Zimmer- und Holzbauarbeiten | Wand | Innenwand 1-Schalig | WI-HW 60 | 0 | A | 3.75 | 1163HWa0812425480 | NEW |  | no | REI 30 | 0 | no | 47 | no | Codetext | AllplanAttributes - ash W_laufende Nr. Statik: 1 (W 1.0/ 1.1/ 1.2); Positionsnummer_Text: U100
 | H2 Ebene +1 | WI-HW 60 | 1163Wa 0814679224 | yes | Codetext | m² | Zimmer- und Holzbauarbeiten | Wand | Innenwand 1-Schalig | WI-HW 60 | 0 | A | 3.75 | 1163HWa0812425480 | NEW |  | no | REI 30 | 0 | no | 47 | no | Codetext | AllplanAttributes - ash W_laufende Nr. Statik: 1 (W 1.0/ 1.1/ 1.2); Positionsnummer_Text: U100
 | H2 Ebene +1 | WI-HW 60 | 1163Wa 0814679244 | yes | Codetext | m² | Zimmer- und Holzbauarbeiten | Wand | Innenwand 1-Schalig | WI-HW 60 | 0 | A | 3.75 | 1163HWa0812425480 | NEW |  | no | REI 30 | 0 | no | 47 | no | Codetext | AllplanAttributes - ash W_laufende Nr. Statik: 1 (W 1.0/ 1.1/ 1.2); Positionsnummer_Text: U100
 | H2 Ebene +1 | WI-LB | 1163Wa 0812447359 | yes | Codetext | m² | Trockenbauarbeiten | Wand | Innenwand 1-Schalig | WI-LB | 0 | A | 3.75 | 1163HWa0812429188 | NEW | no | no | REI 60-A1 - D,s2-d0 /A1 | 0 | no | 0 | no | Codetext | AllplanAttributes - ash_W_Trockenbau_Qualitäten: 6; Positionsnummer_Text: U100
 | H2 Ebene +1 | WI-STB | 1163Wa 0814680560 | yes | Codetext | m² | Zimmer- und Holzbauarbeiten | Wand | Innenwand 1-Schalig | WI-STB | 0 | A | 3.75 | 1163HWa0812430573 | NEW | yes | no | REI 60-A1 - D,s2-d0 /A1 | 0 | no | - | no | Codetext | AllplanAttributes - Positionsnummer_Text: U100
 | H2 Ebene +1 | WI-LB | 1163Wa 0812447378 | yes | Codetext | m² | Trockenbauarbeiten | Wand | Innenwand 1-Schalig | WI-LB | 0 | A | 3.75 | 1163HWa0812447232 | NEW | no | no | 0 | 0 | no |  | no | Codetext | AllplanAttributes - ash_W_Trockenbau_Qualitäten: 9; Sicherheitsklasse: -; Positionsnummer_Text: U100
 | H2 Ebene +1 | WI-STB | 1163Wa 0813792253 | yes | Codetext | m² | Betonarbeiten | Wand | Innenwand 1-Schalig | WI-STB | 0 | A | 3.75 | 1163HWa0812447232 | NEW | yes | no | 0 | 0 | no | 42 | no | Codetext | AllplanAttributes - Sicherheitsklasse: -; Positionsnummer_Text: U100
 | H2 Ebene +1 | WI-LB | 1163Wa 0814681068 | yes | Codetext | m² | Trockenbauarbeiten | Wand | Innenwand 1-Schalig | WI-LB | 0 | A | 3.75 | 1163HWa0812447232 | NEW | no | no | 0 | 0 | no |  | no | Codetext | AllplanAttributes - ash_W_Trockenbau_Qualitäten: 9; Sicherheitsklasse: -; Positionsnummer_Text: U100
 | H2 Ebene +1 | WI-STB | 1163Wa 0812447396 | yes | Codetext | m² | Zimmer- und Holzbauarbeiten | Wand | Innenwand 1-Schalig | WI-STB | 0 | A | 3.75 | 1163HWa0812430804 | NEW | yes | no | REI 60-A1 - D,s2-d0 /A1 | 0 | no | 42 | no | Codetext | AllplanAttributes - Positionsnummer_Text: U100
 | H2 Ebene +1 | WI-LB | 1163Wa 0814681389 | yes | Codetext | m² | Trockenbauarbeiten | Wand | Innenwand 1-Schalig | WI-LB | 0 | A | 3.75 | 1163HWa0812447232 | NEW | no | no | 0 | 0 | no |  | no | Codetext | AllplanAttributes - ash_W_Trockenbau_Qualitäten: 9; Sicherheitsklasse: -; Positionsnummer_Text: U100
 | H2 Ebene +1 | WI-LB | 1163Wa 0812844332 | yes | Codetext | m² | Trockenbauarbeiten | Wand | Innenwand 1-Schalig | WI-LB | 0 | A | 3.75 | 1163HWa0812844331 | NEW | no | no | REI 60-A1 - D,s2-d0 /A1 | 0 | no | 0 | no | Codetext | AllplanAttributes - ash_W_Trockenbau_Qualitäten: 9; Positionsnummer_Text: U100
 | H2 Ebene +1 | WI-LB | 1163Wa 0812953829 | yes | Codetext | m² | Trockenbauarbeiten | Wand | Innenwand 1-Schalig | WI-LB | 0 | A | 3.75 | 1163HWa0812953828 | NEW |  | no | REI 60-A1 - D,s2-d0 /A1 | 0 | no | 0 | no | Codetext | AllplanAttributes - Positionsnummer_Text: U100
 | H2 Ebene +1 | WI-LB | 1163Wa 0814681851 | yes | Codetext | m² | Trockenbauarbeiten | Wand | Innenwand 1-Schalig | WI-LB | 0 | A | 3.75 | 1163HWa0812844331 | NEW | no | no | REI 60-A1 - D,s2-d0 /A1 | 0 | no | 0 | no | Codetext | AllplanAttributes - ash_W_Trockenbau_Qualitäten: 9; Positionsnummer_Text: U100
 | H2 Ebene +1 | WI-LB | 1163Wa 0814681856 | yes | Codetext | m² | Trockenbauarbeiten | Wand | Innenwand 1-Schalig | WI-LB | 0 | A | 3.75 | 1163HWa0812844331 | NEW | no | no | REI 60-A1 - D,s2-d0 /A1 | 0 | no | 0 | no | Codetext | AllplanAttributes - ash_W_Trockenbau_Qualitäten: 6; Positionsnummer_Text: U100
 | H2 Ebene +1 | WI-HW 60 | 1163Wa 0814683568 | yes | Codetext | m² | Zimmer- und Holzbauarbeiten | Wand | Innenwand 1-Schalig | WI-HW 60 | 0 | A | 3.75 | 1163HWa0812434662 | NEW |  | no | REI 60-A1 - D,s2-d0 +A1 | 0 | no | 47 | no | Codetext | AllplanAttributes - ash W_laufende Nr. Statik: 3 (W 3.0); Positionsnummer_Text: U100
 | H2 Ebene +1 | Installationsraum | 1163Wa 0814683569 | yes | Codetext | m² | Trockenbauarbeiten | Wand | Innenwand 1-Schalig | Installationsraum | 0 | A | 0 | 1113HWa0812434427 | NEW |  | no | 0 | 0 | no | 0 | no | Codetext | AllplanAttributes - Sicherheitsklasse: -; Positionsnummer_Text: U100
 | H2 Ebene +1 | WI-LB | 1163Wa 0814683570 | yes | Codetext | m² | Trockenbauarbeiten | Wand | Innenwand 1-Schalig | WI-LB | 0 | A | 3.75 | 1163HWa0812434662 | NEW |  | no | REI 60-A1 - D,s2-d0 /A1 | 0 | no | 0 | no | Codetext | AllplanAttributes - Positionsnummer_Text: U100
WV 1.1 | H2 Ebene +1 |  | 1163Sma0814504586 |  | VUK1 - Lichtleiste (ELT) | St | Trockenbauarbeiten | SmartPart | WV 1.1 |  |  |  | 3.75 |  |  |  |  | - | AllplanAttributes - Text1: WA; UK: 0 m; OK: 0 m; V6: 0 m; V7: 0 m; V8: 0 m; V9: 0; Länge: 1.2 m; Dicke: 0.025 m; Höhe: 0.15 m; Programmversion: 3.1; Text3: 0; Plugin_Bezeichnung: MainObject; Plugin_Objektname: SmartPartCompressed; Version: 1.1; Abstand_Öffn_Unten: 5.375 m; ash T_Feuchtebeständigkeit: nein; Feuerwiderstandsklasse~: nein
WV 1.1 | H2 Ebene +1 |  | 1163Sma0814504382 |  | VUK1 - Lichtleiste (ELT) | St | Trockenbauarbeiten | SmartPart | WV 1.1 |  |  |  | 3.75 |  |  |  |  | - | AllplanAttributes - Text1: WA; UK: 0 m; OK: 0 m; V6: 0 m; V7: 0 m; V8: 0 m; V9: 0; Länge: 1.2 m; Dicke: 0.025 m; Höhe: 0.15 m; Programmversion: 3.1; Text3: 0; Plugin_Bezeichnung: MainObject; Plugin_Objektname: SmartPartCompressed; Version: 1.1; Abstand_Öffn_Unten: 5.375 m; ash T_Feuchtebeständigkeit: nein; Feuerwiderstandsklasse~: nein
WV 1.1 | H2 Ebene +1 |  | 1163Sma0814504463 |  | VUK1 - Lichtleiste (ELT) | St | Trockenbauarbeiten | SmartPart | WV 1.1 |  |  |  | 3.75 |  |  |  |  | - | AllplanAttributes - Text1: WA2003; UK: 0 m; OK: 0 m; V6: 0 m; V7: 0 m; V8: 0 m; V9: 0; Länge: 1.2 m; Dicke: 0.025 m; Höhe: 0.15 m; Programmversion: 3.1; Text3: 0; Plugin_Bezeichnung: MainObject; Plugin_Objektname: SmartPartCompressed; Version: 1.1; Abstand_Öffn_Unten: 5.375 m; ash T_Feuchtebeständigkeit: nein; Feuerwiderstandsklasse~: nein
WV 1.1 | H2 Ebene +1 |  | 1163Sma0814504497 |  | VUK1 - Lichtleiste (ELT) | St | Trockenbauarbeiten | SmartPart | WV 1.1 |  |  |  | 3.75 |  |  |  |  | - | AllplanAttributes - Text1: WA2003; UK: 0 m; OK: 0 m; V6: 0 m; V7: 0 m; V8: 0 m; V9: 0; Länge: 1.2 m; Dicke: 0.025 m; Höhe: 0.15 m; Programmversion: 3.1; Text3: 0; Plugin_Bezeichnung: MainObject; Plugin_Objektname: SmartPartCompressed; Version: 1.1; Abstand_Öffn_Unten: 5.375 m; ash T_Feuchtebeständigkeit: nein; Feuerwiderstandsklasse~: nein
WV 1.1 | H2 Ebene +1 |  | 1163Sma0814504477 |  | VUK1 - Lichtleiste (ELT) | St | Trockenbauarbeiten | SmartPart | WV 1.1 |  |  |  | 3.75 |  |  |  |  | - | AllplanAttributes - Text1: WA2004; UK: 0 m; OK: 0 m; V6: 0 m; V7: 0 m; V8: 0 m; V9: 0; Länge: 1.2 m; Dicke: 0.025 m; Höhe: 0.15 m; Programmversion: 3.1; Text3: 0; Plugin_Bezeichnung: MainObject; Plugin_Objektname: SmartPartCompressed; Version: 1.1; Abstand_Öffn_Unten: 5.375 m; ash T_Feuchtebeständigkeit: nein; Feuerwiderstandsklasse~: nein
WV 1.1 | H2 Ebene +1 |  | 1163Sma0814504521 |  | VUK1 - Lichtleiste (ELT) | St | Trockenbauarbeiten | SmartPart | WV 1.1 |  |  |  | 3.75 |  |  |  |  | - | AllplanAttributes - Text1: WA2004; UK: 0 m; OK: 0 m; V6: 0 m; V7: 0 m; V8: 0 m; V9: 0; Länge: 1.2 m; Dicke: 0.025 m; Höhe: 0.15 m; Programmversion: 3.1; Text3: 0; Plugin_Bezeichnung: MainObject; Plugin_Objektname: SmartPartCompressed; Version: 1.1; Abstand_Öffn_Unten: 5.375 m; ash T_Feuchtebeständigkeit: nein; Feuerwiderstandsklasse~: nein
WV 1.1 | H2 Ebene +1 |  | 1163Sma0814507518 |  | VUK1 - Lichtleiste (ELT) | St | Trockenbauarbeiten | SmartPart | WV 1.1 |  |  |  | 3.75 |  |  |  |  | - | AllplanAttributes - Text1: WA2004; V6: 0 m; V7: 0 m; V8: 0 m; V9: 0; Länge: 1.2 m; Dicke: 0.025 m; Höhe: 0.15 m; Programmversion: 3.1; Text3: 0; Plugin_Bezeichnung: MainObject; Plugin_Objektname: SmartPartCompressed; Version: 1.1; Abstand_Öffn_Unten: 5.375 m; ash T_Feuchtebeständigkeit: nein; Feuerwiderstandsklasse~: nein
WV 1.1 | H2 Ebene +1 |  | 1163Sma0814507531 |  | VUK1 - Lichtleiste (ELT) | St | Trockenbauarbeiten | SmartPart | WV 1.1 |  |  |  | 3.75 |  |  |  |  | - | AllplanAttributes - Text1: WA2002; V6: 0 m; V7: 0 m; V8: 0 m; V9: 0; Länge: 1.2 m; Dicke: 0.025 m; Höhe: 0.15 m; Programmversion: 3.1; Text3: 0; Plugin_Bezeichnung: MainObject; Plugin_Objektname: SmartPartCompressed; Version: 1.1; Abstand_Öffn_Unten: 5.375 m; ash T_Feuchtebeständigkeit: nein; Feuerwiderstandsklasse~: nein
WV 1.1 | H2 Ebene +1 |  | 1163Sma0814504480 |  | VUK1 - Lichtleiste (ELT) | St | Trockenbauarbeiten | SmartPart | WV 1.1 |  |  |  | 3.75 |  |  |  |  | - | AllplanAttributes - Text1: WA2002; UK: 0 m; OK: 0 m; V6: 0 m; V7: 0 m; V8: 0 m; V9: 0; Länge: 1.2 m; Dicke: 0.025 m; Höhe: 0.15 m; Programmversion: 3.1; Text3: 0; Plugin_Bezeichnung: MainObject; Plugin_Objektname: SmartPartCompressed; Version: 1.1; Abstand_Öffn_Unten: 5.375 m; ash T_Feuchtebeständigkeit: nein; Feuerwiderstandsklasse~: nein
WV 1.1 | H2 Ebene +1 |  | 1163Sma0814504583 |  | VUK1 - Lichtleiste (ELT) | St | Trockenbauarbeiten | SmartPart | WV 1.1 |  |  |  | 3.75 |  |  |  |  | - | AllplanAttributes - Text1: WA2001; UK: 0 m; OK: 0 m; V6: 0 m; V7: 0 m; V8: 0 m; V9: 0; Länge: 1.2 m; Dicke: 0.025 m; Höhe: 0.15 m; Programmversion: 3.1; Text3: 0; Plugin_Bezeichnung: MainObject; Plugin_Objektname: SmartPartCompressed; Version: 1.1; Abstand_Öffn_Unten: 5.375 m; ash T_Feuchtebeständigkeit: nein; Feuerwiderstandsklasse~: nein
WV 1.1 | H2 Ebene +1 |  | 1163Sma0814504545 |  | VUK1 - Lichtleiste (ELT) | St | Trockenbauarbeiten | SmartPart | WV 1.1 |  |  |  | 3.75 |  |  |  |  | - | AllplanAttributes - Text1: WA2001; UK: 0 m; OK: 0 m; V6: 0 m; V7: 0 m; V8: 0 m; V9: 0; Länge: 1.2 m; Dicke: 0.025 m; Höhe: 0.15 m; Programmversion: 3.1; Text3: 0; Plugin_Bezeichnung: MainObject; Plugin_Objektname: SmartPartCompressed; Version: 1.1; Abstand_Öffn_Unten: 5.375 m; ash T_Feuchtebeständigkeit: nein; Feuerwiderstandsklasse~: nein
WV 1.1 | H2 Ebene +1 |  | 1163Sma0814504483 |  | VUK1 - Lichtleiste (ELT) | St | Trockenbauarbeiten | SmartPart | WV 1.1 |  |  |  | 3.75 |  |  |  |  | - | AllplanAttributes - Text1: WA2010; UK: 0 m; OK: 0 m; V6: 0 m; V7: 0 m; V8: 0 m; V9: 0; Länge: 1.2 m; Dicke: 0.025 m; Höhe: 0.15 m; Programmversion: 3.1; Text3: 0; Plugin_Bezeichnung: MainObject; Plugin_Objektname: SmartPartCompressed; Version: 1.1; Abstand_Öffn_Unten: 5.375 m; ash T_Feuchtebeständigkeit: nein; Feuerwiderstandsklasse~: nein
WV 1.1 | H2 Ebene +1 |  | 1163Sma0814504569 |  | VUK1 - Lichtleiste (ELT) | St | Trockenbauarbeiten | SmartPart | WV 1.1 |  |  |  | 3.75 |  |  |  |  | - | AllplanAttributes - Text1: WA2010; UK: 0 m; OK: 0 m; V6: 0 m; V7: 0 m; V8: 0 m; V9: 0; Länge: 1.2 m; Dicke: 0.025 m; Höhe: 0.15 m; Programmversion: 3.1; Text3: 0; Plugin_Bezeichnung: MainObject; Plugin_Objektname: SmartPartCompressed; Version: 1.1; Abstand_Öffn_Unten: 5.375 m; ash T_Feuchtebeständigkeit: nein; Feuerwiderstandsklasse~: nein
WV 1.1 | H2 Ebene +1 |  | 1163Sma0814505202 |  | VUK1 - Lichtleiste (ELT) | St | Trockenbauarbeiten | SmartPart | WV 1.1 |  |  |  | 3.75 |  |  |  |  | - | AllplanAttributes - Text1: WA2004; UK: 0 m; OK: 0 m; V6: 0 m; V7: 0 m; V8: 0 m; V9: 0; Länge: 1.2 m; Dicke: 0.025 m; Höhe: 0.15 m; Programmversion: 3.1; Text3: 0; Plugin_Bezeichnung: MainObject; Plugin_Objektname: SmartPartCompressed; Version: 1.1; Abstand_Öffn_Unten: 5.375 m; ash T_Feuchtebeständigkeit: nein; Feuerwiderstandsklasse~: nein
WV 1.1 | H2 Ebene +1 |  | 1163Sma0814505693 |  | VUK1 - Desinfektionsmittelspender | St | Trockenbauarbeiten | SmartPart | WV 1.1 |  |  |  | 3.75 |  |  |  |  | - | AllplanAttributes - Text1: WA2020; UK: 0 m; OK: 0 m; V6: 0 m; V7: 0 m; V8: 0 m; V9: 0; Länge: 0.2 m; Dicke: 0.025 m; Höhe: 0.3 m; Programmversion: 3.1; Text3: 0; Plugin_Bezeichnung: MainObject; Plugin_Objektname: SmartPartCompressed; Version: 1.1; Abstand_Öffn_Unten: 5.01 m; ash T_Feuchtebeständigkeit: nein; Feuerwiderstandsklasse~: nein
WV 1.1 | H2 Ebene +1 |  | 1163Sma0814505645 |  | VUK1 - Hängeschrank | St | Trockenbauarbeiten | SmartPart | WV 1.1 |  |  |  | 3.75 |  |  |  |  | - | AllplanAttributes - Text1: WA2020; UK: 0 m; OK: 0 m; V6: 0 m; V7: 0 m; V8: 0 m; V9: 0; Länge: 0.8 m; Dicke: 0.025 m; Höhe: 0.2 m; Programmversion: 3.1; Text3: 0; Plugin_Bezeichnung: MainObject; Plugin_Objektname: SmartPartCompressed; Version: 1.1; Abstand_Öffn_Unten: 5.75 m; ash T_Feuchtebeständigkeit: nein; Feuerwiderstandsklasse~: nein
WV 1.1 | H2 Ebene +1 |  | 1163Sma0814505742 |  | VUK1 - Hängeschrank | St | Trockenbauarbeiten | SmartPart | WV 1.1 |  |  |  | 3.75 |  |  |  |  | - | AllplanAttributes - Text1: WA2012; UK: 0 m; OK: 0 m; V6: 0 m; V7: 0 m; V8: 0 m; V9: 0; Länge: 2.48 m; Dicke: 0.025 m; Höhe: 0.2 m; Programmversion: 3.1; Text3: 0; Plugin_Bezeichnung: MainObject; Plugin_Objektname: SmartPartCompressed; Version: 1.1; Abstand_Öffn_Unten: 6.1 m; ash T_Feuchtebeständigkeit: nein; Feuerwiderstandsklasse~: nein
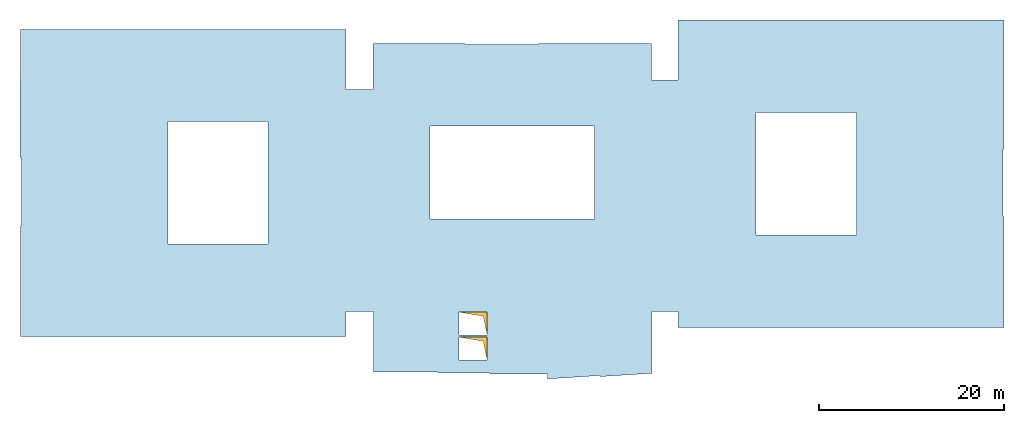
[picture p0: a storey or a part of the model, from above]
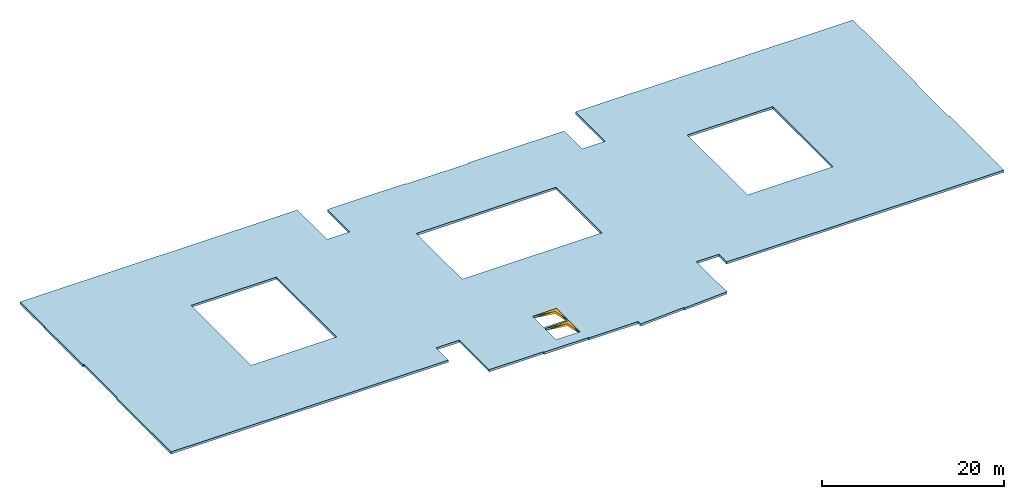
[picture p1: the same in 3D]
Properties of the parts of a building model (IFC4), part 66 of 80

# IfcWall (6826)
Name | In | Material | Allright_Bauteil_ID | 2D Interaktion | Codetext | Abrechnungsart | Gewerk | Objektname | Bezeichnung | AllplanAttributes, Material | Typ = SurfaceSpreadOfFlame | Brandschutzklasse | OKFF | P_ID | Status | LoadBearing | IsExternal | FireRating | ThermalTransmittance (W/K/m2) | Combustible | AcousticRating | Compartmentation | Reference
WV 1.1 | H2 Ebene +1 |  | 1163Sma0814503507 |  | VUK5 - Handlauf | St | Trockenbauarbeiten | SmartPart | WV 1.1 |  |  |  | 3.75 |  |  |  |  | - | AllplanAttributes - Text1: WA; UK: 0 m; OK: 0 m; V6: 0 m; V7: 0 m; V8: 0 m; V9: 0; Länge: 5.5 m; Dicke: 0.025 m; Höhe: 0.2 m; Programmversion: 3.1; Text3: 0; Plugin_Bezeichnung: MainObject; Plugin_Objektname: SmartPartCompressed; Version: 1.1; Abstand_Öffn_Unten: 4.65 m; ash T_Feuchtebeständigkeit: nein; Feuerwiderstandsklasse~: nein
WV 1.1 | H2 Ebene +1 |  | 1163Sma0814689000 |  | VUK2 | St | Trockenbauarbeiten | SmartPart | WV 1.1 |  |  |  | 3.75 |  |  |  |  | - | AllplanAttributes - UK: 0 m; OK: 0 m; V6: 0 m; V7: 0 m; V8: 0 m; V9: 0; Länge: 2.92 m; Dicke: 0.018 m; Höhe: 0.3 m; Programmversion: 3.1; Text3: 0; Plugin_Bezeichnung: MainObject; Plugin_Objektname: SmartPartCompressed; Version: 1.1; Abstand_Öffn_Unten: 6.15 m; ash T_Feuchtebeständigkeit: nein; Feuerwiderstandsklasse~: nein
WV 1.1 | H2 Ebene +1 |  | 1163Sma0814688953 |  | VUK2 | St | Trockenbauarbeiten | SmartPart | WV 1.1 |  |  |  | 3.75 |  |  |  |  | - | AllplanAttributes - UK: 0 m; OK: 0 m; V6: 0 m; V7: 0 m; V8: 0 m; V9: 0; Länge: 2.92 m; Dicke: 0.018 m; Höhe: 0.3 m; Programmversion: 3.1; Text3: 0; Plugin_Bezeichnung: MainObject; Plugin_Objektname: SmartPartCompressed; Version: 1.1; Abstand_Öffn_Unten: 5.35 m; ash T_Feuchtebeständigkeit: nein; Feuerwiderstandsklasse~: nein
WV 1.1 | H2 Ebene +1 |  | 1163Sma0814507453 |  | VUK1 - Lichtleiste (ELT) | St | Trockenbauarbeiten | SmartPart | WV 1.1 |  |  |  | 3.75 |  |  |  |  | - | AllplanAttributes - Text1: WA2001; UK: 0 m; OK: 0 m; V6: 0 m; V7: 0 m; V8: 0 m; V9: 0; Länge: 1.2 m; Dicke: 0.025 m; Höhe: 0.15 m; Programmversion: 3.1; Text3: 0; Plugin_Bezeichnung: MainObject; Plugin_Objektname: SmartPartCompressed; Version: 1.1; Abstand_Öffn_Unten: 5.375 m; ash T_Feuchtebeständigkeit: nein; Feuerwiderstandsklasse~: nein
WV 1.1 | H2 Ebene +1 |  | 1163Sma0814507479 |  | VUK1 - Lichtleiste (ELT) | St | Trockenbauarbeiten | SmartPart | WV 1.1 |  |  |  | 3.75 |  |  |  |  | - | AllplanAttributes - Text1: WA2003; UK: 0 m; OK: 0 m; V6: 0 m; V7: 0 m; V8: 0 m; V9: 0; Länge: 1.2 m; Dicke: 0.025 m; Höhe: 0.15 m; Programmversion: 3.1; Text3: 0; Plugin_Bezeichnung: MainObject; Plugin_Objektname: SmartPartCompressed; Version: 1.1; Abstand_Öffn_Unten: 5.375 m; ash T_Feuchtebeständigkeit: nein; Feuerwiderstandsklasse~: nein
WV 1.1 | H2 Ebene +1 |  | 1163Sma0814507466 |  | VUK1 - Lichtleiste (ELT) | St | Trockenbauarbeiten | SmartPart | WV 1.1 |  |  |  | 3.75 |  |  |  |  | - | AllplanAttributes - Text1: WA2001; UK: 0 m; OK: 0 m; V6: 0 m; V7: 0 m; V8: 0 m; V9: 0; Länge: 1.2 m; Dicke: 0.025 m; Höhe: 0.15 m; Programmversion: 3.1; Text3: 0; Plugin_Bezeichnung: MainObject; Plugin_Objektname: SmartPartCompressed; Version: 1.1; Abstand_Öffn_Unten: 5.375 m; ash T_Feuchtebeständigkeit: nein; Feuerwiderstandsklasse~: nein
WV 1.1 | H2 Ebene +1 |  | 1163Sma0814507492 |  | VUK1 - Lichtleiste (ELT) | St | Trockenbauarbeiten | SmartPart | WV 1.1 |  |  |  | 3.75 |  |  |  |  | - | AllplanAttributes - Text1: WA2003; UK: 0 m; OK: 0 m; V6: 0 m; V7: 0 m; V8: 0 m; V9: 0; Länge: 1.2 m; Dicke: 0.025 m; Höhe: 0.15 m; Programmversion: 3.1; Text3: 0; Plugin_Bezeichnung: MainObject; Plugin_Objektname: SmartPartCompressed; Version: 1.1; Abstand_Öffn_Unten: 5.375 m; ash T_Feuchtebeständigkeit: nein; Feuerwiderstandsklasse~: nein
WV 1.1 | H2 Ebene +1 |  | 1163Sma0814507505 |  | VUK1 - Lichtleiste (ELT) | St | Trockenbauarbeiten | SmartPart | WV 1.1 |  |  |  | 3.75 |  |  |  |  | - | AllplanAttributes - Text1: WA2004; UK: 0 m; OK: 0 m; V6: 0 m; V7: 0 m; V8: 0 m; V9: 0; Länge: 1.2 m; Dicke: 0.025 m; Höhe: 0.15 m; Programmversion: 3.1; Text3: 0; Plugin_Bezeichnung: MainObject; Plugin_Objektname: SmartPartCompressed; Version: 1.1; Abstand_Öffn_Unten: 5.375 m; ash T_Feuchtebeständigkeit: nein; Feuerwiderstandsklasse~: nein
WV 1.1 | H2 Ebene +1 |  | 1163Sma0814507544 |  | VUK1 - Lichtleiste (ELT) | St | Trockenbauarbeiten | SmartPart | WV 1.1 |  |  |  | 3.75 |  |  |  |  | - | AllplanAttributes - Text1: WA2001; UK: 0 m; OK: 0 m; V6: 0 m; V7: 0 m; V8: 0 m; V9: 0; Länge: 1.2 m; Dicke: 0.025 m; Höhe: 0.15 m; Programmversion: 3.1; Text3: 0; Plugin_Bezeichnung: MainObject; Plugin_Objektname: SmartPartCompressed; Version: 1.1; Abstand_Öffn_Unten: 5.375 m; ash T_Feuchtebeständigkeit: nein; Feuerwiderstandsklasse~: nein
WV 1.1 | H2 Ebene +1 |  | 1163Sma0814507570 |  | VUK1 - Lichtleiste (ELT) | St | Trockenbauarbeiten | SmartPart | WV 1.1 |  |  |  | 3.75 |  |  |  |  | - | AllplanAttributes - Text1: WA2001; UK: 0 m; OK: 0 m; V6: 0 m; V7: 0 m; V8: 0 m; V9: 0; Länge: 1.2 m; Dicke: 0.025 m; Höhe: 0.15 m; Programmversion: 3.1; Text3: 0; Plugin_Bezeichnung: MainObject; Plugin_Objektname: SmartPartCompressed; Version: 1.1; Abstand_Öffn_Unten: 5.375 m; ash T_Feuchtebeständigkeit: nein; Feuerwiderstandsklasse~: nein
WV 1.1 | H2 Ebene +1 |  | 1163Sma0814507557 |  | VUK1 - Lichtleiste (ELT) | St | Trockenbauarbeiten | SmartPart | WV 1.1 |  |  |  | 3.75 |  |  |  |  | - | AllplanAttributes - Text1: WA2001; UK: 0 m; OK: 0 m; V6: 0 m; V7: 0 m; V8: 0 m; V9: 0; Länge: 1.2 m; Dicke: 0.025 m; Höhe: 0.15 m; Programmversion: 3.1; Text3: 0; Plugin_Bezeichnung: MainObject; Plugin_Objektname: SmartPartCompressed; Version: 1.1; Abstand_Öffn_Unten: 5.375 m; ash T_Feuchtebeständigkeit: nein; Feuerwiderstandsklasse~: nein
WV 1.1 | H2 Ebene +1 |  | 1163Sma0814507797 |  | VUK1 - Lichtleiste (ELT) | St | Trockenbauarbeiten | SmartPart | WV 1.1 |  |  |  | 3.75 |  |  |  |  | - | AllplanAttributes - Text1: WA2001; UK: 0 m; OK: 0 m; V6: 0 m; V7: 0 m; V8: 0 m; V9: 0; Länge: 1.2 m; Dicke: 0.025 m; Höhe: 0.15 m; Programmversion: 3.1; Text3: 0; Plugin_Bezeichnung: MainObject; Plugin_Objektname: SmartPartCompressed; Version: 1.1; Abstand_Öffn_Unten: 5.375 m; ash T_Feuchtebeständigkeit: nein; Feuerwiderstandsklasse~: nein
WV 1.1 | H2 Ebene +1 |  | 1163Sma0814507917 |  | VUK1 - Lichtleiste (ELT) | St | Trockenbauarbeiten | SmartPart | WV 1.1 |  |  |  | 3.75 |  |  |  |  | - | AllplanAttributes - Text1: WA2010; UK: 0 m; OK: 0 m; V6: 0 m; V7: 0 m; V8: 0 m; V9: 0; Länge: 1.2 m; Dicke: 0.025 m; Höhe: 0.15 m; Programmversion: 3.1; Text3: 0; Plugin_Bezeichnung: MainObject; Plugin_Objektname: SmartPartCompressed; Version: 1.1; Abstand_Öffn_Unten: 5.375 m; ash T_Feuchtebeständigkeit: nein; Feuerwiderstandsklasse~: nein
WV 1.1 | H2 Ebene +1 |  | 1163Sma0814507930 |  | VUK1 - Lichtleiste (ELT) | St | Trockenbauarbeiten | SmartPart | WV 1.1 |  |  |  | 3.75 |  |  |  |  | - | AllplanAttributes - Text1: WA2010; UK: 0 m; OK: 0 m; V6: 0 m; V7: 0 m; V8: 0 m; V9: 0; Länge: 1.2 m; Dicke: 0.025 m; Höhe: 0.15 m; Programmversion: 3.1; Text3: 0; Plugin_Bezeichnung: MainObject; Plugin_Objektname: SmartPartCompressed; Version: 1.1; Abstand_Öffn_Unten: 5.375 m; ash T_Feuchtebeständigkeit: nein; Feuerwiderstandsklasse~: nein
WV 1.1 | H2 Ebene +1 |  | 1163Sma0814503973 |  | VUK5 - Handlauf | St | Trockenbauarbeiten | SmartPart | WV 1.1 |  |  |  | 3.75 |  |  |  |  | - | AllplanAttributes - Text1: WA; UK: 0 m; OK: 0 m; V6: 0 m; V7: 0 m; V8: 0 m; V9: 0; Länge: 1.5 m; Dicke: 0.025 m; Höhe: 0.2 m; Programmversion: 3.1; Text3: 0; Plugin_Bezeichnung: MainObject; Plugin_Objektname: SmartPartCompressed; Version: 1.1; Abstand_Öffn_Unten: 4.65 m; ash T_Feuchtebeständigkeit: nein; Feuerwiderstandsklasse~: nein
WV 1.1 | H2 Ebene +1 |  | 1163Sma0814504013 |  | VUK5 - Handlauf | St | Trockenbauarbeiten | SmartPart | WV 1.1 |  |  |  | 3.75 |  |  |  |  | - | AllplanAttributes - Text1: WA; UK: 0 m; OK: 0 m; V6: 0 m; V7: 0 m; V8: 0 m; V9: 0; Länge: 1.5 m; Dicke: 0.025 m; Höhe: 0.2 m; Programmversion: 3.1; Text3: 0; Plugin_Bezeichnung: MainObject; Plugin_Objektname: SmartPartCompressed; Version: 1.1; Abstand_Öffn_Unten: 4.65 m; ash T_Feuchtebeständigkeit: nein; Feuerwiderstandsklasse~: nein
WV 1.1 | H2 Ebene +1 |  | 1163Sma0814504064 |  | VUK5 - Handlauf | St | Trockenbauarbeiten | SmartPart | WV 1.1 |  |  |  | 3.75 |  |  |  |  | - | AllplanAttributes - Text1: WA; UK: 0 m; OK: 0 m; V6: 0 m; V7: 0 m; V8: 0 m; V9: 0; Länge: 1.5 m; Dicke: 0.025 m; Höhe: 0.2 m; Programmversion: 3.1; Text3: 0; Plugin_Bezeichnung: MainObject; Plugin_Objektname: SmartPartCompressed; Version: 1.1; Abstand_Öffn_Unten: 4.65 m; ash T_Feuchtebeständigkeit: nein; Feuerwiderstandsklasse~: nein
WV 1.1 | H2 Ebene +1 |  | 1163Sma0814504050 |  | VUK5 - Handlauf | St | Trockenbauarbeiten | SmartPart | WV 1.1 |  |  |  | 3.75 |  |  |  |  | - | AllplanAttributes - Text1: WA; UK: 0 m; OK: 0 m; V6: 0 m; V7: 0 m; V8: 0 m; V9: 0; Länge: 1.5 m; Dicke: 0.025 m; Höhe: 0.2 m; Programmversion: 3.1; Text3: 0; Plugin_Bezeichnung: MainObject; Plugin_Objektname: SmartPartCompressed; Version: 1.1; Abstand_Öffn_Unten: 4.65 m; ash T_Feuchtebeständigkeit: nein; Feuerwiderstandsklasse~: nein
WV 1.1 | H2 Ebene +1 |  | 1163Sma0814505387 |  | VUK1 - Monitor | St | Trockenbauarbeiten | SmartPart | WV 1.1 |  |  |  | 3.75 |  |  |  |  | - | AllplanAttributes - Text1: WA2030; UK: 0 m; OK: 0 m; V6: 0 m; V7: 0 m; V8: 0 m; V9: 0; Länge: 1.2 m; Dicke: 0.025 m; Höhe: 1 m; Programmversion: 3.1; Text3: 0; Plugin_Bezeichnung: MainObject; Plugin_Objektname: SmartPartCompressed; Version: 1.1; Abstand_Öffn_Unten: 4.85 m; ash T_Feuchtebeständigkeit: nein; Feuerwiderstandsklasse~: nein
WV 1.1 | H2 Ebene +1 |  | 1163Sma0814505943 |  | VUK1 - Haltegriff | St | Trockenbauarbeiten | SmartPart | WV 1.1 |  |  |  | 3.75 |  |  |  |  | - | AllplanAttributes - Text1: WA2018; UK: 0 m; OK: 0 m; V6: 0 m; V7: 0 m; V8: 0 m; V9: 0; Länge: 1.6 m; Dicke: 0.025 m; Höhe: 0.2 m; Programmversion: 3.1; Text3: 0; Plugin_Bezeichnung: MainObject; Plugin_Objektname: SmartPartCompressed; Version: 1.1; Abstand_Öffn_Unten: 5.3 m; ash T_Feuchtebeständigkeit: nein; Feuerwiderstandsklasse~: nein
WV 1.1 | H2 Ebene +1 |  | 1163Sma0814688792 |  | VUK1 - Desinfektionsmittelspender | St | Trockenbauarbeiten | SmartPart | WV 1.1 |  |  |  | 3.75 |  |  |  |  | - | AllplanAttributes - Text1: WA2020; UK: 0 m; OK: 0 m; V6: 0 m; V7: 0 m; V8: 0 m; V9: 0; Länge: 0.3 m; Dicke: 0.025 m; Höhe: 0.7 m; Programmversion: 3.1; Text3: 0; Plugin_Bezeichnung: MainObject; Plugin_Objektname: SmartPartCompressed; Version: 1.1; Abstand_Öffn_Unten: 4.6 m; ash T_Feuchtebeständigkeit: nein; Feuerwiderstandsklasse~: nein
WV 1.1 | H2 Ebene +1 |  | 1163Sma0814508141 |  | VUK1 - Lichtleiste (ELT) | St | Trockenbauarbeiten | SmartPart | WV 1.1 |  |  |  | 3.75 |  |  |  |  | - | AllplanAttributes - Text1: WA2001; UK: 0 m; OK: 0 m; V6: 0 m; V7: 0 m; V8: 0 m; V9: 0; Länge: 1.2 m; Dicke: 0.025 m; Höhe: 0.15 m; Programmversion: 3.1; Text3: 0; Plugin_Bezeichnung: MainObject; Plugin_Objektname: SmartPartCompressed; Version: 1.1; Abstand_Öffn_Unten: 5.375 m; ash T_Feuchtebeständigkeit: nein; Feuerwiderstandsklasse~: nein
WV 1.1 | H2 Ebene +1 |  | 1163Sma0814508165 |  | VUK1 - Lichtleiste (ELT) | St | Trockenbauarbeiten | SmartPart | WV 1.1 |  |  |  | 3.75 |  |  |  |  | - | AllplanAttributes - Text1: WA2001; UK: 0 m; OK: 0 m; V6: 0 m; V7: 0 m; V8: 0 m; V9: 0; Länge: 1.2 m; Dicke: 0.025 m; Höhe: 0.15 m; Programmversion: 3.1; Text3: 0; Plugin_Bezeichnung: MainObject; Plugin_Objektname: SmartPartCompressed; Version: 1.1; Abstand_Öffn_Unten: 5.375 m; ash T_Feuchtebeständigkeit: nein; Feuerwiderstandsklasse~: nein
WV 1.1 | H2 Ebene +1 |  | 1163Sma0814508143 |  | VUK1 - Lichtleiste (ELT) | St | Trockenbauarbeiten | SmartPart | WV 1.1 |  |  |  | 3.75 |  |  |  |  | - | AllplanAttributes - Text1: WA2001; UK: 0 m; OK: 0 m; V6: 0 m; V7: 0 m; V8: 0 m; V9: 0; Länge: 1.2 m; Dicke: 0.025 m; Höhe: 0.15 m; Programmversion: 3.1; Text3: 0; Plugin_Bezeichnung: MainObject; Plugin_Objektname: SmartPartCompressed; Version: 1.1; Abstand_Öffn_Unten: 5.375 m; ash T_Feuchtebeständigkeit: nein; Feuerwiderstandsklasse~: nein
WV 1.1 | H2 Ebene +1 |  | 1163Sma0814508145 |  | VUK1 - Lichtleiste (ELT) | St | Trockenbauarbeiten | SmartPart | WV 1.1 |  |  |  | 3.75 |  |  |  |  | - | AllplanAttributes - Text1: WA2001; UK: 0 m; OK: 0 m; V6: 0 m; V7: 0 m; V8: 0 m; V9: 0; Länge: 1.2 m; Dicke: 0.025 m; Höhe: 0.15 m; Programmversion: 3.1; Text3: 0; Plugin_Bezeichnung: MainObject; Plugin_Objektname: SmartPartCompressed; Version: 1.1; Abstand_Öffn_Unten: 5.375 m; ash T_Feuchtebeständigkeit: nein; Feuerwiderstandsklasse~: nein
WV 1.1 | H2 Ebene +1 |  | 1163Sma0814508163 |  | VUK1 - Lichtleiste (ELT) | St | Trockenbauarbeiten | SmartPart | WV 1.1 |  |  |  | 3.75 |  |  |  |  | - | AllplanAttributes - Text1: WA2001; UK: 0 m; OK: 0 m; V6: 0 m; V7: 0 m; V8: 0 m; V9: 0; Länge: 1.2 m; Dicke: 0.025 m; Höhe: 0.15 m; Programmversion: 3.1; Text3: 0; Plugin_Bezeichnung: MainObject; Plugin_Objektname: SmartPartCompressed; Version: 1.1; Abstand_Öffn_Unten: 5.375 m; ash T_Feuchtebeständigkeit: nein; Feuerwiderstandsklasse~: nein
WV 1.1 | H2 Ebene +1 |  | 1163Sma0814508161 |  | VUK1 - Lichtleiste (ELT) | St | Trockenbauarbeiten | SmartPart | WV 1.1 |  |  |  | 3.75 |  |  |  |  | - | AllplanAttributes - Text1: WA2001; UK: 0 m; OK: 0 m; V6: 0 m; V7: 0 m; V8: 0 m; V9: 0; Länge: 1.2 m; Dicke: 0.025 m; Höhe: 0.15 m; Programmversion: 3.1; Text3: 0; Plugin_Bezeichnung: MainObject; Plugin_Objektname: SmartPartCompressed; Version: 1.1; Abstand_Öffn_Unten: 5.375 m; ash T_Feuchtebeständigkeit: nein; Feuerwiderstandsklasse~: nein
WV 1.1 | H2 Ebene +1 |  | 1163Sma0814508147 |  | VUK1 - Lichtleiste (ELT) | St | Trockenbauarbeiten | SmartPart | WV 1.1 |  |  |  | 3.75 |  |  |  |  | - | AllplanAttributes - Text1: WA2001; UK: 0 m; OK: 0 m; V6: 0 m; V7: 0 m; V8: 0 m; V9: 0; Länge: 1.2 m; Dicke: 0.025 m; Höhe: 0.15 m; Programmversion: 3.1; Text3: 0; Plugin_Bezeichnung: MainObject; Plugin_Objektname: SmartPartCompressed; Version: 1.1; Abstand_Öffn_Unten: 5.375 m; ash T_Feuchtebeständigkeit: nein; Feuerwiderstandsklasse~: nein
WV 1.1 | H2 Ebene +1 |  | 1163Sma0814508159 |  | VUK1 - Lichtleiste (ELT) | St | Trockenbauarbeiten | SmartPart | WV 1.1 |  |  |  | 3.75 |  |  |  |  | - | AllplanAttributes - Text1: WA2001; UK: 0 m; OK: 0 m; V6: 0 m; V7: 0 m; V8: 0 m; V9: 0; Länge: 1.2 m; Dicke: 0.025 m; Höhe: 0.15 m; Programmversion: 3.1; Text3: 0; Plugin_Bezeichnung: MainObject; Plugin_Objektname: SmartPartCompressed; Version: 1.1; Abstand_Öffn_Unten: 5.375 m; ash T_Feuchtebeständigkeit: nein; Feuerwiderstandsklasse~: nein
WV 1.1 | H2 Ebene +1 |  | 1163Sma0814508149 |  | VUK1 - Lichtleiste (ELT) | St | Trockenbauarbeiten | SmartPart | WV 1.1 |  |  |  | 3.75 |  |  |  |  | - | AllplanAttributes - Text1: WA2001; UK: 0 m; OK: 0 m; V6: 0 m; V7: 0 m; V8: 0 m; V9: 0; Länge: 1.2 m; Dicke: 0.025 m; Höhe: 0.15 m; Programmversion: 3.1; Text3: 0; Plugin_Bezeichnung: MainObject; Plugin_Objektname: SmartPartCompressed; Version: 1.1; Abstand_Öffn_Unten: 5.375 m; ash T_Feuchtebeständigkeit: nein; Feuerwiderstandsklasse~: nein
WV 1.1 | H2 Ebene +1 |  | 1163Sma0814508157 |  | VUK1 - Lichtleiste (ELT) | St | Trockenbauarbeiten | SmartPart | WV 1.1 |  |  |  | 3.75 |  |  |  |  | - | AllplanAttributes - Text1: WA2001; UK: 0 m; OK: 0 m; V6: 0 m; V7: 0 m; V8: 0 m; V9: 0; Länge: 1.2 m; Dicke: 0.025 m; Höhe: 0.15 m; Programmversion: 3.1; Text3: 0; Plugin_Bezeichnung: MainObject; Plugin_Objektname: SmartPartCompressed; Version: 1.1; Abstand_Öffn_Unten: 5.375 m; ash T_Feuchtebeständigkeit: nein; Feuerwiderstandsklasse~: nein
WV 1.1 | H2 Ebene +1 |  | 1163Sma0814508151 |  | VUK1 - Lichtleiste (ELT) | St | Trockenbauarbeiten | SmartPart | WV 1.1 |  |  |  | 3.75 |  |  |  |  | - | AllplanAttributes - Text1: WA2001; UK: 0 m; OK: 0 m; V6: 0 m; V7: 0 m; V8: 0 m; V9: 0; Länge: 1.2 m; Dicke: 0.025 m; Höhe: 0.15 m; Programmversion: 3.1; Text3: 0; Plugin_Bezeichnung: MainObject; Plugin_Objektname: SmartPartCompressed; Version: 1.1; Abstand_Öffn_Unten: 5.375 m; ash T_Feuchtebeständigkeit: nein; Feuerwiderstandsklasse~: nein
WV 1.1 | H2 Ebene +1 |  | 1163Sma0814508155 |  | VUK1 - Lichtleiste (ELT) | St | Trockenbauarbeiten | SmartPart | WV 1.1 |  |  |  | 3.75 |  |  |  |  | - | AllplanAttributes - Text1: WA2001; UK: 0 m; OK: 0 m; V6: 0 m; V7: 0 m; V8: 0 m; V9: 0; Länge: 1.2 m; Dicke: 0.025 m; Höhe: 0.15 m; Programmversion: 3.1; Text3: 0; Plugin_Bezeichnung: MainObject; Plugin_Objektname: SmartPartCompressed; Version: 1.1; Abstand_Öffn_Unten: 5.375 m; ash T_Feuchtebeständigkeit: nein; Feuerwiderstandsklasse~: nein
WV 1.1 | H2 Ebene +1 |  | 1163Sma0814508153 |  | VUK1 - Lichtleiste (ELT) | St | Trockenbauarbeiten | SmartPart | WV 1.1 |  |  |  | 3.75 |  |  |  |  | - | AllplanAttributes - Text1: WA2001; UK: 0 m; OK: 0 m; V6: 0 m; V7: 0 m; V8: 0 m; V9: 0; Länge: 1.2 m; Dicke: 0.025 m; Höhe: 0.15 m; Programmversion: 3.1; Text3: 0; Plugin_Bezeichnung: MainObject; Plugin_Objektname: SmartPartCompressed; Version: 1.1; Abstand_Öffn_Unten: 5.375 m; ash T_Feuchtebeständigkeit: nein; Feuerwiderstandsklasse~: nein
WV 1.1 | H2 Ebene +1 |  | 1163Sma0814504093 |  | VUK5 - Handlauf | St | Trockenbauarbeiten | SmartPart | WV 1.1 |  |  |  | 3.75 |  |  |  |  | - | AllplanAttributes - Text1: WA; UK: 0 m; OK: 0 m; V6: 0 m; V7: 0 m; V8: 0 m; V9: 0; Länge: 5.4 m; Dicke: 0.025 m; Höhe: 0.2 m; Programmversion: 3.1; Text3: 0; Plugin_Bezeichnung: MainObject; Plugin_Objektname: SmartPartCompressed; Version: 1.1; Abstand_Öffn_Unten: 4.65 m; ash T_Feuchtebeständigkeit: nein; Feuerwiderstandsklasse~: nein
WV 1.1 | H2 Ebene +1 |  | 1163Sma0814504128 |  | VUK5 - Handlauf | St | Trockenbauarbeiten | SmartPart | WV 1.1 |  |  |  | 3.75 |  |  |  |  | - | AllplanAttributes - Text1: WA; UK: 0 m; OK: 0 m; V6: 0 m; V7: 0 m; V8: 0 m; V9: 0; Länge: 0.7 m; Dicke: 0.025 m; Höhe: 0.2 m; Programmversion: 3.1; Text3: 0; Plugin_Bezeichnung: MainObject; Plugin_Objektname: SmartPartCompressed; Version: 1.1; Abstand_Öffn_Unten: 4.65 m; ash T_Feuchtebeständigkeit: nein; Feuerwiderstandsklasse~: nein
WV 1.1 | H2 Ebene +1 |  | 1163Sma0814506731 |  | VUK1 - Hängeschrank | St | Trockenbauarbeiten | SmartPart | WV 1.1 |  |  |  | 3.75 |  |  |  |  | - | AllplanAttributes - Text1: WA2012; UK: 0 m; OK: 0 m; V6: 0 m; V7: 0 m; V8: 0 m; V9: 0; Länge: 2.46 m; Dicke: 0.025 m; Höhe: 0.2 m; Programmversion: 3.1; Text3: 0; Plugin_Bezeichnung: MainObject; Plugin_Objektname: SmartPartCompressed; Version: 1.1; Abstand_Öffn_Unten: 6.1 m; ash T_Feuchtebeständigkeit: nein; Feuerwiderstandsklasse~: nein
WV 1.1 | H2 Ebene +1 |  | 1163Sma0814506971 |  | VUK1 - Hängeschrank | St | Trockenbauarbeiten | SmartPart | WV 1.1 |  |  |  | 3.75 |  |  |  |  | - | AllplanAttributes - Text1: WA2020; UK: 0 m; OK: 0 m; V6: 0 m; V7: 0 m; V8: 0 m; V9: 0; Länge: 0.8 m; Dicke: 0.025 m; Höhe: 0.2 m; Programmversion: 3.1; Text3: 0; Plugin_Bezeichnung: MainObject; Plugin_Objektname: SmartPartCompressed; Version: 1.1; Abstand_Öffn_Unten: 5.95 m; ash T_Feuchtebeständigkeit: nein; Feuerwiderstandsklasse~: nein
WV 1.1 | H2 Ebene +1 |  | 1163Sma0814508869 |  | VUK1 - Lichtleiste (ELT) | St | Trockenbauarbeiten | SmartPart | WV 1.1 |  |  |  | 3.75 |  |  |  |  | - | AllplanAttributes - Text1: WA2001; UK: 0 m; OK: 0 m; V6: 0 m; V7: 0 m; V8: 0 m; V9: 0; Länge: 1.2 m; Dicke: 0.025 m; Höhe: 0.15 m; Programmversion: 3.1; Text3: 0; Plugin_Bezeichnung: MainObject; Plugin_Objektname: SmartPartCompressed; Version: 1.1; Abstand_Öffn_Unten: 5.375 m; ash T_Feuchtebeständigkeit: nein; Feuerwiderstandsklasse~: nein
WV 1.1 | H2 Ebene +1 |  | 1163Sma0814508882 |  | VUK1 - Lichtleiste (ELT) | St | Trockenbauarbeiten | SmartPart | WV 1.1 |  |  |  | 3.75 |  |  |  |  | - | AllplanAttributes - Text1: WA2001; UK: 0 m; OK: 0 m; V6: 0 m; V7: 0 m; V8: 0 m; V9: 0; Länge: 1.2 m; Dicke: 0.025 m; Höhe: 0.15 m; Programmversion: 3.1; Text3: 0; Plugin_Bezeichnung: MainObject; Plugin_Objektname: SmartPartCompressed; Version: 1.1; Abstand_Öffn_Unten: 5.375 m; ash T_Feuchtebeständigkeit: nein; Feuerwiderstandsklasse~: nein
WV 1.1 | H2 Ebene +1 |  | 1163Sma0814508895 |  | VUK1 - Lichtleiste (ELT) | St | Trockenbauarbeiten | SmartPart | WV 1.1 |  |  |  | 3.75 |  |  |  |  | - | AllplanAttributes - Text1: WA2001; UK: 0 m; OK: 0 m; V6: 0 m; V7: 0 m; V8: 0 m; V9: 0; Länge: 1.2 m; Dicke: 0.025 m; Höhe: 0.15 m; Programmversion: 3.1; Text3: 0; Plugin_Bezeichnung: MainObject; Plugin_Objektname: SmartPartCompressed; Version: 1.1; Abstand_Öffn_Unten: 5.375 m; ash T_Feuchtebeständigkeit: nein; Feuerwiderstandsklasse~: nein
WV 1.1 | H2 Ebene +1 |  | 1163Sma0814508908 |  | VUK1 - Lichtleiste (ELT) | St | Trockenbauarbeiten | SmartPart | WV 1.1 |  |  |  | 3.75 |  |  |  |  | - | AllplanAttributes - Text1: WA2001; UK: 0 m; OK: 0 m; V6: 0 m; V7: 0 m; V8: 0 m; V9: 0; Länge: 1.2 m; Dicke: 0.025 m; Höhe: 0.15 m; Programmversion: 3.1; Text3: 0; Plugin_Bezeichnung: MainObject; Plugin_Objektname: SmartPartCompressed; Version: 1.1; Abstand_Öffn_Unten: 5.375 m; ash T_Feuchtebeständigkeit: nein; Feuerwiderstandsklasse~: nein
WV 1.1 | H2 Ebene +1 |  | 1163Sma0814508921 |  | VUK1 - Lichtleiste (ELT) | St | Trockenbauarbeiten | SmartPart | WV 1.1 |  |  |  | 3.75 |  |  |  |  | - | AllplanAttributes - Text1: WA2001; UK: 0 m; OK: 0 m; V6: 0 m; V7: 0 m; V8: 0 m; V9: 0; Länge: 1.2 m; Dicke: 0.025 m; Höhe: 0.15 m; Programmversion: 3.1; Text3: 0; Plugin_Bezeichnung: MainObject; Plugin_Objektname: SmartPartCompressed; Version: 1.1; Abstand_Öffn_Unten: 5.375 m; ash T_Feuchtebeständigkeit: nein; Feuerwiderstandsklasse~: nein
WV 1.1 | H2 Ebene +1 |  | 1163Sma0814508934 |  | VUK1 - Lichtleiste (ELT) | St | Trockenbauarbeiten | SmartPart | WV 1.1 |  |  |  | 3.75 |  |  |  |  | - | AllplanAttributes - Text1: WA2001; UK: 0 m; OK: 0 m; V6: 0 m; V7: 0 m; V8: 0 m; V9: 0; Länge: 1.2 m; Dicke: 0.025 m; Höhe: 0.15 m; Programmversion: 3.1; Text3: 0; Plugin_Bezeichnung: MainObject; Plugin_Objektname: SmartPartCompressed; Version: 1.1; Abstand_Öffn_Unten: 5.375 m; ash T_Feuchtebeständigkeit: nein; Feuerwiderstandsklasse~: nein
WV 1.1 | H2 Ebene +1 |  | 1163Sma0814508947 |  | VUK1 - Lichtleiste (ELT) | St | Trockenbauarbeiten | SmartPart | WV 1.1 |  |  |  | 3.75 |  |  |  |  | - | AllplanAttributes - Text1: WA2001; UK: 0 m; OK: 0 m; V6: 0 m; V7: 0 m; V8: 0 m; V9: 0; Länge: 1.2 m; Dicke: 0.025 m; Höhe: 0.15 m; Programmversion: 3.1; Text3: 0; Plugin_Bezeichnung: MainObject; Plugin_Objektname: SmartPartCompressed; Version: 1.1; Abstand_Öffn_Unten: 5.375 m; ash T_Feuchtebeständigkeit: nein; Feuerwiderstandsklasse~: nein
WV 1.1 | H2 Ebene +1 |  | 1163Sma0814508960 |  | VUK1 - Lichtleiste (ELT) | St | Trockenbauarbeiten | SmartPart | WV 1.1 |  |  |  | 3.75 |  |  |  |  | - | AllplanAttributes - Text1: WA2001; UK: 0 m; OK: 0 m; V6: 0 m; V7: 0 m; V8: 0 m; V9: 0; Länge: 1.2 m; Dicke: 0.025 m; Höhe: 0.15 m; Programmversion: 3.1; Text3: 0; Plugin_Bezeichnung: MainObject; Plugin_Objektname: SmartPartCompressed; Version: 1.1; Abstand_Öffn_Unten: 5.375 m; ash T_Feuchtebeständigkeit: nein; Feuerwiderstandsklasse~: nein
WV 1.1 | H2 Ebene +1 |  | 1163Sma0814508973 |  | VUK1 - Lichtleiste (ELT) | St | Trockenbauarbeiten | SmartPart | WV 1.1 |  |  |  | 3.75 |  |  |  |  | - | AllplanAttributes - Text1: WA2001; UK: 0 m; OK: 0 m; V6: 0 m; V7: 0 m; V8: 0 m; V9: 0; Länge: 1.2 m; Dicke: 0.025 m; Höhe: 0.15 m; Programmversion: 3.1; Text3: 0; Plugin_Bezeichnung: MainObject; Plugin_Objektname: SmartPartCompressed; Version: 1.1; Abstand_Öffn_Unten: 5.375 m; ash T_Feuchtebeständigkeit: nein; Feuerwiderstandsklasse~: nein
WV 1.1 | H2 Ebene +1 |  | 1163Sma0814508986 |  | VUK1 - Lichtleiste (ELT) | St | Trockenbauarbeiten | SmartPart | WV 1.1 |  |  |  | 3.75 |  |  |  |  | - | AllplanAttributes - Text1: WA2001; UK: 0 m; OK: 0 m; V6: 0 m; V7: 0 m; V8: 0 m; V9: 0; Länge: 1.2 m; Dicke: 0.025 m; Höhe: 0.15 m; Programmversion: 3.1; Text3: 0; Plugin_Bezeichnung: MainObject; Plugin_Objektname: SmartPartCompressed; Version: 1.1; Abstand_Öffn_Unten: 5.375 m; ash T_Feuchtebeständigkeit: nein; Feuerwiderstandsklasse~: nein
WV 1.1 | H2 Ebene +1 |  | 1163Sma0814508999 |  | VUK1 - Lichtleiste (ELT) | St | Trockenbauarbeiten | SmartPart | WV 1.1 |  |  |  | 3.75 |  |  |  |  | - | AllplanAttributes - Text1: WA2001; UK: 0 m; OK: 0 m; V6: 0 m; V7: 0 m; V8: 0 m; V9: 0; Länge: 1.2 m; Dicke: 0.025 m; Höhe: 0.15 m; Programmversion: 3.1; Text3: 0; Plugin_Bezeichnung: MainObject; Plugin_Objektname: SmartPartCompressed; Version: 1.1; Abstand_Öffn_Unten: 5.375 m; ash T_Feuchtebeständigkeit: nein; Feuerwiderstandsklasse~: nein
WV 1.1 | H2 Ebene +1 |  | 1163Sma0814509012 |  | VUK1 - Lichtleiste (ELT) | St | Trockenbauarbeiten | SmartPart | WV 1.1 |  |  |  | 3.75 |  |  |  |  | - | AllplanAttributes - Text1: WA2001; UK: 0 m; OK: 0 m; V6: 0 m; V7: 0 m; V8: 0 m; V9: 0; Länge: 1.2 m; Dicke: 0.025 m; Höhe: 0.15 m; Programmversion: 3.1; Text3: 0; Plugin_Bezeichnung: MainObject; Plugin_Objektname: SmartPartCompressed; Version: 1.1; Abstand_Öffn_Unten: 5.375 m; ash T_Feuchtebeständigkeit: nein; Feuerwiderstandsklasse~: nein
WV 1.1 | H2 Ebene +1 |  | 1163Sma0814509025 |  | VUK1 - Lichtleiste (ELT) | St | Trockenbauarbeiten | SmartPart | WV 1.1 |  |  |  | 3.75 |  |  |  |  | - | AllplanAttributes - Text1: WA2001; UK: 0 m; OK: 0 m; V6: 0 m; V7: 0 m; V8: 0 m; V9: 0; Länge: 1.2 m; Dicke: 0.025 m; Höhe: 0.15 m; Programmversion: 3.1; Text3: 0; Plugin_Bezeichnung: MainObject; Plugin_Objektname: SmartPartCompressed; Version: 1.1; Abstand_Öffn_Unten: 5.375 m; ash T_Feuchtebeständigkeit: nein; Feuerwiderstandsklasse~: nein
WV 1.1 | H2 Ebene +1 |  | 1163Sma0814690363 |  | VUK1 - Desinfektionsmittelspender | St | Trockenbauarbeiten | SmartPart | WV 1.1 |  |  |  | 3.75 |  |  |  |  | - | AllplanAttributes - Text1: WA2020; UK: 0 m; OK: 0 m; V6: 0 m; V7: 0 m; V8: 0 m; V9: 0; Länge: 0.3 m; Dicke: 0.025 m; Höhe: 0.7 m; Programmversion: 3.1; Text3: 0; Plugin_Bezeichnung: MainObject; Plugin_Objektname: SmartPartCompressed; Version: 1.1; Abstand_Öffn_Unten: 4.55 m; ash T_Feuchtebeständigkeit: nein; Feuerwiderstandsklasse~: nein
WV 1.1 | H2 Ebene +1 |  | 1163Sma0814690388 |  | VUK1 - Desinfektionsmittelspender | St | Trockenbauarbeiten | SmartPart | WV 1.1 |  |  |  | 3.75 |  |  |  |  | - | AllplanAttributes - Text1: WA2020; UK: 0 m; OK: 0 m; V6: 0 m; V7: 0 m; V8: 0 m; V9: 0; Länge: 0.3 m; Dicke: 0.025 m; Höhe: 0.7 m; Programmversion: 3.1; Text3: 0; Plugin_Bezeichnung: MainObject; Plugin_Objektname: SmartPartCompressed; Version: 1.1; Abstand_Öffn_Unten: 4.55 m; ash T_Feuchtebeständigkeit: nein; Feuerwiderstandsklasse~: nein
WV 1.1 | H2 Ebene +1 |  | 1163Sma0814505266 |  | VUK1 - Hängeschrank | St | Trockenbauarbeiten | SmartPart | WV 1.1 |  |  |  | 3.75 |  |  |  |  | - | AllplanAttributes - Text1: WA2008; UK: 0 m; OK: 0 m; V6: 0 m; V7: 0 m; V8: 0 m; V9: 0; Länge: 4.65 m; Dicke: 0.025 m; Höhe: 0.2 m; Programmversion: 3.1; Text3: 0; Plugin_Bezeichnung: MainObject; Plugin_Objektname: SmartPartCompressed; Version: 1.1; Abstand_Öffn_Unten: 6.1 m; ash T_Feuchtebeständigkeit: nein; Feuerwiderstandsklasse~: nein
WV 1.1 | H2 Ebene +1 |  | 1163Sma0814505425 |  | VUK1 - Monitor | St | Trockenbauarbeiten | SmartPart | WV 1.1 |  |  |  | 3.75 |  |  |  |  | - | AllplanAttributes - Text1: WA2030; UK: 0 m; OK: 0 m; V6: 0 m; V7: 0 m; V8: 0 m; V9: 0; Länge: 1.2 m; Dicke: 0.025 m; Höhe: 1 m; Programmversion: 3.1; Text3: 0; Plugin_Bezeichnung: MainObject; Plugin_Objektname: SmartPartCompressed; Version: 1.1; Abstand_Öffn_Unten: 4.85 m; ash T_Feuchtebeständigkeit: nein; Feuerwiderstandsklasse~: nein
WV 1.1 | H2 Ebene +1 |  | 1163Sma0814691220 |  | VUK1 | St | Trockenbauarbeiten | SmartPart | WV 1.1 |  |  |  | 3.75 |  |  |  |  | - | AllplanAttributes - UK: 0 m; OK: 0 m; V6: 0 m; V7: 0 m; V8: 0 m; V9: 0; Länge: 0.2 m; Dicke: 0.025 m; Höhe: 0.4 m; Programmversion: 3.1; Text3: 0; Plugin_Bezeichnung: MainObject; Plugin_Objektname: SmartPartCompressed; Version: 1.1; Abstand_Öffn_Unten: 4.38 m; ash T_Feuchtebeständigkeit: nein; Feuerwiderstandsklasse~: nein
WV 1.1 | H2 Ebene +1 |  | 1163Sma0814691121 |  | VUK1 - Feuerlöscher | St | Trockenbauarbeiten | SmartPart | WV 1.1 |  |  |  | 3.75 |  |  |  |  | - | AllplanAttributes - UK: 0 m; OK: 0 m; V6: 0 m; V7: 0 m; V8: 0 m; V9: 0; Länge: 0.3 m; Dicke: 0.025 m; Höhe: 0.7 m; Programmversion: 3.1; Text3: 0; Plugin_Bezeichnung: MainObject; Plugin_Objektname: SmartPartCompressed; Version: 1.1; Abstand_Öffn_Unten: 4.55 m; ash T_Feuchtebeständigkeit: nein; Feuerwiderstandsklasse~: nein
WV 1.1 | H2 Ebene +1 |  | 1163Sma0814691146 |  | VUK1 - Feuerlöcher | St | Trockenbauarbeiten | SmartPart | WV 1.1 |  |  |  | 3.75 |  |  |  |  | - | AllplanAttributes - UK: 0 m; OK: 0 m; V6: 0 m; V7: 0 m; V8: 0 m; V9: 0; Länge: 0.3 m; Dicke: 0.025 m; Höhe: 0.7 m; Programmversion: 3.1; Text3: 0; Plugin_Bezeichnung: MainObject; Plugin_Objektname: SmartPartCompressed; Version: 1.1; Abstand_Öffn_Unten: 4.55 m; ash T_Feuchtebeständigkeit: nein; Feuerwiderstandsklasse~: nein
WV 1.1 | H2 Ebene +1 |  | 1163Sma0814688767 |  | VUK1 - Feuerlöcher | St | Trockenbauarbeiten | SmartPart | WV 1.1 |  |  |  | 3.75 |  |  |  |  | - | AllplanAttributes - UK: 0 m; OK: 0 m; V6: 0 m; V7: 0 m; V8: 0 m; V9: 0; Länge: 0.3 m; Dicke: 0.025 m; Höhe: 0.7 m; Programmversion: 3.1; Text3: 0; Plugin_Bezeichnung: MainObject; Plugin_Objektname: SmartPartCompressed; Version: 1.1; Abstand_Öffn_Unten: 4.55 m; ash T_Feuchtebeständigkeit: nein; Feuerwiderstandsklasse~: nein
WV 1.1 | H2 Ebene +1 |  | 1163Sma0814688742 |  | VUK1 - Feuerlöcher | St | Trockenbauarbeiten | SmartPart | WV 1.1 |  |  |  | 3.75 |  |  |  |  | - | AllplanAttributes - UK: 0 m; OK: 0 m; V6: 0 m; V7: 0 m; V8: 0 m; V9: 0; Länge: 0.3 m; Dicke: 0.025 m; Höhe: 0.7 m; Programmversion: 3.1; Text3: 0; Plugin_Bezeichnung: MainObject; Plugin_Objektname: SmartPartCompressed; Version: 1.1; Abstand_Öffn_Unten: 4.55 m; ash T_Feuchtebeständigkeit: nein; Feuerwiderstandsklasse~: nein
WV 1.1 | H2 Ebene +1 |  | 1163Sma0814688658 |  | VUK1 - Feuerlöcher | St | Trockenbauarbeiten | SmartPart | WV 1.1 |  |  |  | 3.75 |  |  |  |  | - | AllplanAttributes - UK: 0 m; OK: 0 m; V6: 0 m; V7: 0 m; V8: 0 m; V9: 0; Länge: 0.3 m; Dicke: 0.025 m; Höhe: 0.7 m; Programmversion: 3.1; Text3: 0; Plugin_Bezeichnung: MainObject; Plugin_Objektname: SmartPartCompressed; Version: 1.1; Abstand_Öffn_Unten: 4.55 m; ash T_Feuchtebeständigkeit: nein; Feuerwiderstandsklasse~: nein
WV 1.1 | H2 Ebene +1 |  | 1163Sma0814691171 |  | VUK1 - Feuerlöscher | St | Trockenbauarbeiten | SmartPart | WV 1.1 |  |  |  | 3.75 |  |  |  |  | - | AllplanAttributes - UK: 0 m; OK: 0 m; V6: 0 m; V7: 0 m; V8: 0 m; V9: 0; Länge: 0.3 m; Dicke: 0.025 m; Höhe: 0.7 m; Programmversion: 3.1; Text3: 0; Plugin_Bezeichnung: MainObject; Plugin_Objektname: SmartPartCompressed; Version: 1.1; Abstand_Öffn_Unten: 4.55 m; ash T_Feuchtebeständigkeit: nein; Feuerwiderstandsklasse~: nein
WV 1.1 | H2 Ebene +1 |  | 1163Sma0814688838 |  | VUK1 - Feuerlöcher | St | Trockenbauarbeiten | SmartPart | WV 1.1 |  |  |  | 3.75 |  |  |  |  | - | AllplanAttributes - UK: 0 m; OK: 0 m; V6: 0 m; V7: 0 m; V8: 0 m; V9: 0; Länge: 0.3 m; Dicke: 0.025 m; Höhe: 0.7 m; Programmversion: 3.1; Text3: 0; Plugin_Bezeichnung: MainObject; Plugin_Objektname: SmartPartCompressed; Version: 1.1; Abstand_Öffn_Unten: 4.55 m; ash T_Feuchtebeständigkeit: nein; Feuerwiderstandsklasse~: nein
WV 1.1 | H2 Ebene +1 |  | 1163Sma0814688815 |  | VUK1 - Feuerlöcher | St | Trockenbauarbeiten | SmartPart | WV 1.1 |  |  |  | 3.75 |  |  |  |  | - | AllplanAttributes - UK: 0 m; OK: 0 m; V6: 0 m; V7: 0 m; V8: 0 m; V9: 0; Länge: 0.3 m; Dicke: 0.025 m; Höhe: 0.7 m; Programmversion: 3.1; Text3: 0; Plugin_Bezeichnung: MainObject; Plugin_Objektname: SmartPartCompressed; Version: 1.1; Abstand_Öffn_Unten: 4.55 m; ash T_Feuchtebeständigkeit: nein; Feuerwiderstandsklasse~: nein
WV 1.1 | H2 Ebene +1 |  | 1163Sma0814689696 |  | VUK1 - Feuerlöcher | St | Trockenbauarbeiten | SmartPart | WV 1.1 |  |  |  | 3.75 |  |  |  |  | - | AllplanAttributes - UK: 0 m; OK: 0 m; V6: 0 m; V7: 0 m; V8: 0 m; V9: 0; Länge: 0.3 m; Dicke: 0.025 m; Höhe: 0.7 m; Programmversion: 3.1; Text3: 0; Plugin_Bezeichnung: MainObject; Plugin_Objektname: SmartPartCompressed; Version: 1.1; Abstand_Öffn_Unten: 4.55 m; ash T_Feuchtebeständigkeit: nein; Feuerwiderstandsklasse~: nein
WV 1.1 | H2 Ebene +1 |  | 1163Sma0814692198 |  | VUK2 | St | Trockenbauarbeiten | SmartPart | WV 1.1 |  |  |  | 3.75 |  |  |  |  | - | AllplanAttributes - UK: 0 m; OK: 0 m; V6: 0 m; V7: 0 m; V8: 0 m; V9: 0; Länge: 2.82 m; Dicke: 0.018 m; Höhe: 0.3 m; Programmversion: 3.1; Text3: 0; Plugin_Bezeichnung: MainObject; Plugin_Objektname: SmartPartCompressed; Version: 1.1; Abstand_Öffn_Unten: 6.15 m; ash T_Feuchtebeständigkeit: nein; Feuerwiderstandsklasse~: nein
WV 1.1 | H2 Ebene +1 |  | 1163Sma0814692211 |  | VUK2 | St | Trockenbauarbeiten | SmartPart | WV 1.1 |  |  |  | 3.75 |  |  |  |  | - | AllplanAttributes - UK: 0 m; OK: 0 m; V6: 0 m; V7: 0 m; V8: 0 m; V9: 0; Länge: 2.82 m; Dicke: 0.018 m; Höhe: 0.3 m; Programmversion: 3.1; Text3: 0; Plugin_Bezeichnung: MainObject; Plugin_Objektname: SmartPartCompressed; Version: 1.1; Abstand_Öffn_Unten: 5.35 m; ash T_Feuchtebeständigkeit: nein; Feuerwiderstandsklasse~: nein
WV 1.1 | H2 Ebene +1 |  | 1163Sma0814692150 |  | VUK2 | St | Trockenbauarbeiten | SmartPart | WV 1.1 |  |  |  | 3.75 |  |  |  |  | - | AllplanAttributes - UK: 0 m; OK: 0 m; V6: 0 m; V7: 0 m; V8: 0 m; V9: 0; Länge: 0.35 m; Dicke: 0.018 m; Höhe: 0.3 m; Programmversion: 3.1; Text3: 0; Plugin_Bezeichnung: MainObject; Plugin_Objektname: SmartPartCompressed; Version: 1.1; Abstand_Öffn_Unten: 6.15 m; ash T_Feuchtebeständigkeit: nein; Feuerwiderstandsklasse~: nein
WV 1.1 | H2 Ebene +1 |  | 1163Sma0814692163 |  | VUK2 | St | Trockenbauarbeiten | SmartPart | WV 1.1 |  |  |  | 3.75 |  |  |  |  | - | AllplanAttributes - UK: 0 m; OK: 0 m; V6: 0 m; V7: 0 m; V8: 0 m; V9: 0; Länge: 0.35 m; Dicke: 0.018 m; Höhe: 0.3 m; Programmversion: 3.1; Text3: 0; Plugin_Bezeichnung: MainObject; Plugin_Objektname: SmartPartCompressed; Version: 1.1; Abstand_Öffn_Unten: 5.35 m; ash T_Feuchtebeständigkeit: nein; Feuerwiderstandsklasse~: nein
WV 1.1 | H2 Ebene +1 |  | 1163Sma0814692388 |  | VUK2 | St | Trockenbauarbeiten | SmartPart | WV 1.1 |  |  |  | 3.75 |  |  |  |  | - | AllplanAttributes - UK: 0 m; OK: 0 m; V6: 0 m; V7: 0 m; V8: 0 m; V9: 0; Länge: 0.59 m; Dicke: 0.018 m; Höhe: 0.3 m; Programmversion: 3.1; Text3: 0; Plugin_Bezeichnung: MainObject; Plugin_Objektname: SmartPartCompressed; Version: 1.1; Abstand_Öffn_Unten: 6.15 m; ash T_Feuchtebeständigkeit: nein; Feuerwiderstandsklasse~: nein
WV 1.1 | H2 Ebene +1 |  | 1163Sma0814692390 |  | VUK2 | St | Trockenbauarbeiten | SmartPart | WV 1.1 |  |  |  | 3.75 |  |  |  |  | - | AllplanAttributes - UK: 0 m; OK: 0 m; V6: 0 m; V7: 0 m; V8: 0 m; V9: 0; Länge: 0.59 m; Dicke: 0.018 m; Höhe: 0.3 m; Programmversion: 3.1; Text3: 0; Plugin_Bezeichnung: MainObject; Plugin_Objektname: SmartPartCompressed; Version: 1.1; Abstand_Öffn_Unten: 5.35 m; ash T_Feuchtebeständigkeit: nein; Feuerwiderstandsklasse~: nein
WV 1.1 | H2 Ebene +1 |  | 1163Sma0814692342 |  | VUK2 | St | Trockenbauarbeiten | SmartPart | WV 1.1 |  |  |  | 3.75 |  |  |  |  | - | AllplanAttributes - UK: 0 m; OK: 0 m; V6: 0 m; V7: 0 m; V8: 0 m; V9: 0; Länge: 0.5 m; Dicke: 0.018 m; Höhe: 0.3 m; Programmversion: 3.1; Text3: 0; Plugin_Bezeichnung: MainObject; Plugin_Objektname: SmartPartCompressed; Version: 1.1; Abstand_Öffn_Unten: 6.15 m; ash T_Feuchtebeständigkeit: nein; Feuerwiderstandsklasse~: nein
WV 1.1 | H2 Ebene +1 |  | 1163Sma0814692344 |  | VUK2 | St | Trockenbauarbeiten | SmartPart | WV 1.1 |  |  |  | 3.75 |  |  |  |  | - | AllplanAttributes - UK: 0 m; OK: 0 m; V6: 0 m; V7: 0 m; V8: 0 m; V9: 0; Länge: 0.5 m; Dicke: 0.018 m; Höhe: 0.3 m; Programmversion: 3.1; Text3: 0; Plugin_Bezeichnung: MainObject; Plugin_Objektname: SmartPartCompressed; Version: 1.1; Abstand_Öffn_Unten: 5.35 m; ash T_Feuchtebeständigkeit: nein; Feuerwiderstandsklasse~: nein
WV 1.1 | H2 Ebene +1 |  | 1163Sma0814692296 |  | VUK2 | St | Trockenbauarbeiten | SmartPart | WV 1.1 |  |  |  | 3.75 |  |  |  |  | - | AllplanAttributes - UK: 0 m; OK: 0 m; V6: 0 m; V7: 0 m; V8: 0 m; V9: 0; Länge: 0.74 m; Dicke: 0.018 m; Höhe: 0.3 m; Programmversion: 3.1; Text3: 0; Plugin_Bezeichnung: MainObject; Plugin_Objektname: SmartPartCompressed; Version: 1.1; Abstand_Öffn_Unten: 6.15 m; ash T_Feuchtebeständigkeit: nein; Feuerwiderstandsklasse~: nein
WV 1.1 | H2 Ebene +1 |  | 1163Sma0814692298 |  | VUK2 | St | Trockenbauarbeiten | SmartPart | WV 1.1 |  |  |  | 3.75 |  |  |  |  | - | AllplanAttributes - UK: 0 m; OK: 0 m; V6: 0 m; V7: 0 m; V8: 0 m; V9: 0; Länge: 0.74 m; Dicke: 0.018 m; Höhe: 0.3 m; Programmversion: 3.1; Text3: 0; Plugin_Bezeichnung: MainObject; Plugin_Objektname: SmartPartCompressed; Version: 1.1; Abstand_Öffn_Unten: 5.35 m; ash T_Feuchtebeständigkeit: nein; Feuerwiderstandsklasse~: nein
WV 1.1 | H2 Ebene +1 |  | 1163Sma0814692603 |  | VUK2 | St | Trockenbauarbeiten | SmartPart | WV 1.1 |  |  |  | 3.75 |  |  |  |  | - | AllplanAttributes - UK: 0 m; OK: 0 m; V6: 0 m; V7: 0 m; V8: 0 m; V9: 0; Länge: 2.82 m; Dicke: 0.018 m; Höhe: 0.3 m; Programmversion: 3.1; Text3: 0; Plugin_Bezeichnung: MainObject; Plugin_Objektname: SmartPartCompressed; Version: 1.1; Abstand_Öffn_Unten: 6.15 m; ash T_Feuchtebeständigkeit: nein; Feuerwiderstandsklasse~: nein
WV 1.1 | H2 Ebene +1 |  | 1163Sma0814692605 |  | VUK2 | St | Trockenbauarbeiten | SmartPart | WV 1.1 |  |  |  | 3.75 |  |  |  |  | - | AllplanAttributes - UK: 0 m; OK: 0 m; V6: 0 m; V7: 0 m; V8: 0 m; V9: 0; Länge: 2.82 m; Dicke: 0.018 m; Höhe: 0.3 m; Programmversion: 3.1; Text3: 0; Plugin_Bezeichnung: MainObject; Plugin_Objektname: SmartPartCompressed; Version: 1.1; Abstand_Öffn_Unten: 5.35 m; ash T_Feuchtebeständigkeit: nein; Feuerwiderstandsklasse~: nein
WV 1.1 | H2 Ebene +1 |  | 1163Sma0814692651 |  | VUK2 | St | Trockenbauarbeiten | SmartPart | WV 1.1 |  |  |  | 3.75 |  |  |  |  | - | AllplanAttributes - UK: 0 m; OK: 0 m; V6: 0 m; V7: 0 m; V8: 0 m; V9: 0; Länge: 2.82 m; Dicke: 0.018 m; Höhe: 0.3 m; Programmversion: 3.1; Text3: 0; Plugin_Bezeichnung: MainObject; Plugin_Objektname: SmartPartCompressed; Version: 1.1; Abstand_Öffn_Unten: 6.15 m; ash T_Feuchtebeständigkeit: nein; Feuerwiderstandsklasse~: nein
WV 1.1 | H2 Ebene +1 |  | 1163Sma0814692653 |  | VUK2 | St | Trockenbauarbeiten | SmartPart | WV 1.1 |  |  |  | 3.75 |  |  |  |  | - | AllplanAttributes - UK: 0 m; OK: 0 m; V6: 0 m; V7: 0 m; V8: 0 m; V9: 0; Länge: 2.82 m; Dicke: 0.018 m; Höhe: 0.3 m; Programmversion: 3.1; Text3: 0; Plugin_Bezeichnung: MainObject; Plugin_Objektname: SmartPartCompressed; Version: 1.1; Abstand_Öffn_Unten: 5.35 m; ash T_Feuchtebeständigkeit: nein; Feuerwiderstandsklasse~: nein
WV 1.1 | H2 Ebene +1 |  | 1163Sma0814692700 |  | VUK2 | St | Trockenbauarbeiten | SmartPart | WV 1.1 |  |  |  | 3.75 |  |  |  |  | - | AllplanAttributes - UK: 0 m; OK: 0 m; V6: 0 m; V7: 0 m; V8: 0 m; V9: 0; Länge: 2.82 m; Dicke: 0.018 m; Höhe: 0.3 m; Programmversion: 3.1; Text3: 0; Plugin_Bezeichnung: MainObject; Plugin_Objektname: SmartPartCompressed; Version: 1.1; Abstand_Öffn_Unten: 6.15 m; ash T_Feuchtebeständigkeit: nein; Feuerwiderstandsklasse~: nein
WV 1.1 | H2 Ebene +1 |  | 1163Sma0814692702 |  | VUK2 | St | Trockenbauarbeiten | SmartPart | WV 1.1 |  |  |  | 3.75 |  |  |  |  | - | AllplanAttributes - UK: 0 m; OK: 0 m; V6: 0 m; V7: 0 m; V8: 0 m; V9: 0; Länge: 2.82 m; Dicke: 0.018 m; Höhe: 0.3 m; Programmversion: 3.1; Text3: 0; Plugin_Bezeichnung: MainObject; Plugin_Objektname: SmartPartCompressed; Version: 1.1; Abstand_Öffn_Unten: 5.35 m; ash T_Feuchtebeständigkeit: nein; Feuerwiderstandsklasse~: nein
WV 1.1 | H2 Ebene +1 |  | 1163Sma0814692904 |  | VUK2 | St | Trockenbauarbeiten | SmartPart | WV 1.1 |  |  |  | 3.75 |  |  |  |  | - | AllplanAttributes - UK: 0 m; OK: 0 m; V6: 0 m; V7: 0 m; V8: 0 m; V9: 0; Länge: 2.82 m; Dicke: 0.018 m; Höhe: 0.3 m; Programmversion: 3.1; Text3: 0; Plugin_Bezeichnung: MainObject; Plugin_Objektname: SmartPartCompressed; Version: 1.1; Abstand_Öffn_Unten: 6.15 m; ash T_Feuchtebeständigkeit: nein; Feuerwiderstandsklasse~: nein
WV 1.1 | H2 Ebene +1 |  | 1163Sma0814692906 |  | VUK2 | St | Trockenbauarbeiten | SmartPart | WV 1.1 |  |  |  | 3.75 |  |  |  |  | - | AllplanAttributes - UK: 0 m; OK: 0 m; V6: 0 m; V7: 0 m; V8: 0 m; V9: 0; Länge: 2.82 m; Dicke: 0.018 m; Höhe: 0.3 m; Programmversion: 3.1; Text3: 0; Plugin_Bezeichnung: MainObject; Plugin_Objektname: SmartPartCompressed; Version: 1.1; Abstand_Öffn_Unten: 5.35 m; ash T_Feuchtebeständigkeit: nein; Feuerwiderstandsklasse~: nein
WV 1.1 | H2 Ebene +1 |  | 1163Sma0814693039 |  | VUK2 | St | Trockenbauarbeiten | SmartPart | WV 1.1 |  |  |  | 3.75 |  |  |  |  | - | AllplanAttributes - UK: 0 m; OK: 0 m; V6: 0 m; V7: 0 m; V8: 0 m; V9: 0; Länge: 2.82 m; Dicke: 0.018 m; Höhe: 0.3 m; Programmversion: 3.1; Text3: 0; Plugin_Bezeichnung: MainObject; Plugin_Objektname: SmartPartCompressed; Version: 1.1; Abstand_Öffn_Unten: 6.15 m; ash T_Feuchtebeständigkeit: nein; Feuerwiderstandsklasse~: nein
WV 1.1 | H2 Ebene +1 |  | 1163Sma0814693041 |  | VUK2 | St | Trockenbauarbeiten | SmartPart | WV 1.1 |  |  |  | 3.75 |  |  |  |  | - | AllplanAttributes - UK: 0 m; OK: 0 m; V6: 0 m; V7: 0 m; V8: 0 m; V9: 0; Länge: 2.82 m; Dicke: 0.018 m; Höhe: 0.3 m; Programmversion: 3.1; Text3: 0; Plugin_Bezeichnung: MainObject; Plugin_Objektname: SmartPartCompressed; Version: 1.1; Abstand_Öffn_Unten: 5.35 m; ash T_Feuchtebeständigkeit: nein; Feuerwiderstandsklasse~: nein
WV 1.1 | H2 Ebene +1 |  | 1163Sma0814693066 |  | VUK2 | St | Trockenbauarbeiten | SmartPart | WV 1.1 |  |  |  | 3.75 |  |  |  |  | - | AllplanAttributes - UK: 0 m; OK: 0 m; V6: 0 m; V7: 0 m; V8: 0 m; V9: 0; Länge: 2.82 m; Dicke: 0.018 m; Höhe: 0.3 m; Programmversion: 3.1; Text3: 0; Plugin_Bezeichnung: MainObject; Plugin_Objektname: SmartPartCompressed; Version: 1.1; Abstand_Öffn_Unten: 6.15 m; ash T_Feuchtebeständigkeit: nein; Feuerwiderstandsklasse~: nein
WV 1.1 | H2 Ebene +1 |  | 1163Sma0814693068 |  | VUK2 | St | Trockenbauarbeiten | SmartPart | WV 1.1 |  |  |  | 3.75 |  |  |  |  | - | AllplanAttributes - UK: 0 m; OK: 0 m; V6: 0 m; V7: 0 m; V8: 0 m; V9: 0; Länge: 2.82 m; Dicke: 0.018 m; Höhe: 0.3 m; Programmversion: 3.1; Text3: 0; Plugin_Bezeichnung: MainObject; Plugin_Objektname: SmartPartCompressed; Version: 1.1; Abstand_Öffn_Unten: 5.35 m; ash T_Feuchtebeständigkeit: nein; Feuerwiderstandsklasse~: nein
WV 1.1 | H2 Ebene +1 |  | 1163Sma0814693093 |  | VUK2 | St | Trockenbauarbeiten | SmartPart | WV 1.1 |  |  |  | 3.75 |  |  |  |  | - | AllplanAttributes - UK: 0 m; OK: 0 m; V6: 0 m; V7: 0 m; V8: 0 m; V9: 0; Länge: 2.82 m; Dicke: 0.018 m; Höhe: 0.3 m; Programmversion: 3.1; Text3: 0; Plugin_Bezeichnung: MainObject; Plugin_Objektname: SmartPartCompressed; Version: 1.1; Abstand_Öffn_Unten: 6.15 m; ash T_Feuchtebeständigkeit: nein; Feuerwiderstandsklasse~: nein
WV 1.1 | H2 Ebene +1 |  | 1163Sma0814693095 |  | VUK2 | St | Trockenbauarbeiten | SmartPart | WV 1.1 |  |  |  | 3.75 |  |  |  |  | - | AllplanAttributes - UK: 0 m; OK: 0 m; V6: 0 m; V7: 0 m; V8: 0 m; V9: 0; Länge: 2.82 m; Dicke: 0.018 m; Höhe: 0.3 m; Programmversion: 3.1; Text3: 0; Plugin_Bezeichnung: MainObject; Plugin_Objektname: SmartPartCompressed; Version: 1.1; Abstand_Öffn_Unten: 5.35 m; ash T_Feuchtebeständigkeit: nein; Feuerwiderstandsklasse~: nein
WV 1.1 | H2 Ebene +1 |  | 1163Sma0814692931 |  | VUK2 | St | Trockenbauarbeiten | SmartPart | WV 1.1 |  |  |  | 3.75 |  |  |  |  | - | AllplanAttributes - UK: 0 m; OK: 0 m; V6: 0 m; V7: 0 m; V8: 0 m; V9: 0; Länge: 0.59 m; Dicke: 0.018 m; Höhe: 0.3 m; Programmversion: 3.1; Text3: 0; Plugin_Bezeichnung: MainObject; Plugin_Objektname: SmartPartCompressed; Version: 1.1; Abstand_Öffn_Unten: 6.15 m; ash T_Feuchtebeständigkeit: nein; Feuerwiderstandsklasse~: nein
WV 1.1 | H2 Ebene +1 |  | 1163Sma0814692933 |  | VUK2 | St | Trockenbauarbeiten | SmartPart | WV 1.1 |  |  |  | 3.75 |  |  |  |  | - | AllplanAttributes - UK: 0 m; OK: 0 m; V6: 0 m; V7: 0 m; V8: 0 m; V9: 0; Länge: 0.59 m; Dicke: 0.018 m; Höhe: 0.3 m; Programmversion: 3.1; Text3: 0; Plugin_Bezeichnung: MainObject; Plugin_Objektname: SmartPartCompressed; Version: 1.1; Abstand_Öffn_Unten: 5.35 m; ash T_Feuchtebeständigkeit: nein; Feuerwiderstandsklasse~: nein
WV 1.1 | H2 Ebene +1 |  | 1163Sma0814693012 |  | VUK2 | St | Trockenbauarbeiten | SmartPart | WV 1.1 |  |  |  | 3.75 |  |  |  |  | - | AllplanAttributes - UK: 0 m; OK: 0 m; V6: 0 m; V7: 0 m; V8: 0 m; V9: 0; Länge: 0.5 m; Dicke: 0.018 m; Höhe: 0.3 m; Programmversion: 3.1; Text3: 0; Plugin_Bezeichnung: MainObject; Plugin_Objektname: SmartPartCompressed; Version: 1.1; Abstand_Öffn_Unten: 6.15 m; ash T_Feuchtebeständigkeit: nein; Feuerwiderstandsklasse~: nein
WV 1.1 | H2 Ebene +1 |  | 1163Sma0814693014 |  | VUK2 | St | Trockenbauarbeiten | SmartPart | WV 1.1 |  |  |  | 3.75 |  |  |  |  | - | AllplanAttributes - UK: 0 m; OK: 0 m; V6: 0 m; V7: 0 m; V8: 0 m; V9: 0; Länge: 0.5 m; Dicke: 0.018 m; Höhe: 0.3 m; Programmversion: 3.1; Text3: 0; Plugin_Bezeichnung: MainObject; Plugin_Objektname: SmartPartCompressed; Version: 1.1; Abstand_Öffn_Unten: 5.35 m; ash T_Feuchtebeständigkeit: nein; Feuerwiderstandsklasse~: nein
WV 1.1 | H2 Ebene +1 |  | 1163Sma0814692984 |  | VUK2 | St | Trockenbauarbeiten | SmartPart | WV 1.1 |  |  |  | 3.75 |  |  |  |  | - | AllplanAttributes - UK: 0 m; OK: 0 m; V6: 0 m; V7: 0 m; V8: 0 m; V9: 0; Länge: 0.59 m; Dicke: 0.018 m; Höhe: 0.3 m; Programmversion: 3.1; Text3: 0; Plugin_Bezeichnung: MainObject; Plugin_Objektname: SmartPartCompressed; Version: 1.1; Abstand_Öffn_Unten: 6.15 m; ash T_Feuchtebeständigkeit: nein; Feuerwiderstandsklasse~: nein
WV 1.1 | H2 Ebene +1 |  | 1163Sma0814692986 |  | VUK2 | St | Trockenbauarbeiten | SmartPart | WV 1.1 |  |  |  | 3.75 |  |  |  |  | - | AllplanAttributes - UK: 0 m; OK: 0 m; V6: 0 m; V7: 0 m; V8: 0 m; V9: 0; Länge: 0.59 m; Dicke: 0.018 m; Höhe: 0.3 m; Programmversion: 3.1; Text3: 0; Plugin_Bezeichnung: MainObject; Plugin_Objektname: SmartPartCompressed; Version: 1.1; Abstand_Öffn_Unten: 5.35 m; ash T_Feuchtebeständigkeit: nein; Feuerwiderstandsklasse~: nein
WV 1.1 | H2 Ebene +1 |  | 1163Sma0814692958 |  | VUK2 | St | Trockenbauarbeiten | SmartPart | WV 1.1 |  |  |  | 3.75 |  |  |  |  | - | AllplanAttributes - UK: 0 m; OK: 0 m; V6: 0 m; V7: 0 m; V8: 0 m; V9: 0; Länge: 0.5 m; Dicke: 0.018 m; Höhe: 0.3 m; Programmversion: 3.1; Text3: 0; Plugin_Bezeichnung: MainObject; Plugin_Objektname: SmartPartCompressed; Version: 1.1; Abstand_Öffn_Unten: 6.15 m; ash T_Feuchtebeständigkeit: nein; Feuerwiderstandsklasse~: nein
WV 1.1 | H2 Ebene +1 |  | 1163Sma0814692971 |  | VUK2 | St | Trockenbauarbeiten | SmartPart | WV 1.1 |  |  |  | 3.75 |  |  |  |  | - | AllplanAttributes - UK: 0 m; OK: 0 m; V6: 0 m; V7: 0 m; V8: 0 m; V9: 0; Länge: 0.5 m; Dicke: 0.018 m; Höhe: 0.3 m; Programmversion: 3.1; Text3: 0; Plugin_Bezeichnung: MainObject; Plugin_Objektname: SmartPartCompressed; Version: 1.1; Abstand_Öffn_Unten: 5.35 m; ash T_Feuchtebeständigkeit: nein; Feuerwiderstandsklasse~: nein
WV 1.1 | H2 Ebene +1 |  | 1163Sma0814693292 |  | VUK2 | St | Trockenbauarbeiten | SmartPart | WV 1.1 |  |  |  | 3.75 |  |  |  |  | - | AllplanAttributes - UK: 0 m; OK: 0 m; V6: 0 m; V7: 0 m; V8: 0 m; V9: 0; Länge: 2.92 m; Dicke: 0.018 m; Höhe: 0.3 m; Programmversion: 3.1; Text3: 0; Plugin_Bezeichnung: MainObject; Plugin_Objektname: SmartPartCompressed; Version: 1.1; Abstand_Öffn_Unten: 6.15 m; ash T_Feuchtebeständigkeit: nein; Feuerwiderstandsklasse~: nein
WV 1.1 | H2 Ebene +1 |  | 1163Sma0814693305 |  | VUK2 | St | Trockenbauarbeiten | SmartPart | WV 1.1 |  |  |  | 3.75 |  |  |  |  | - | AllplanAttributes - UK: 0 m; OK: 0 m; V6: 0 m; V7: 0 m; V8: 0 m; V9: 0; Länge: 2.92 m; Dicke: 0.018 m; Höhe: 0.3 m; Programmversion: 3.1; Text3: 0; Plugin_Bezeichnung: MainObject; Plugin_Objektname: SmartPartCompressed; Version: 1.1; Abstand_Öffn_Unten: 5.35 m; ash T_Feuchtebeständigkeit: nein; Feuerwiderstandsklasse~: nein
WV 1.1 | H2 Ebene +1 |  | 1163Sma0814702936 |  | VUK1 - Desinfektionsmittelspender | St | Trockenbauarbeiten | SmartPart | WV 1.1 |  |  |  | 3.75 |  |  |  |  | - | AllplanAttributes - Text1: WA2018; UK: 0 m; OK: 0 m; V6: 0 m; V7: 0 m; V8: 0 m; V9: 0; Länge: 1.21 m; Dicke: 0.025 m; Höhe: 0.25 m; Programmversion: 3.1; Text3: 0; Plugin_Bezeichnung: MainObject; Plugin_Objektname: SmartPartCompressed; Version: 1.1; Abstand_Öffn_Unten: 3.75 m; ash T_Feuchtebeständigkeit: nein; Feuerwiderstandsklasse~: nein
WV 1.1 | H2 Ebene +1 |  | 1163Sma0814702994 |  | VUK1 - Desinfektionsmittelspender | St | Trockenbauarbeiten | SmartPart | WV 1.1 |  |  |  | 3.75 |  |  |  |  | - | AllplanAttributes - Text1: WA2018; UK: 0 m; OK: 0 m; V6: 0 m; V7: 0 m; V8: 0 m; V9: 0; Länge: 1.21 m; Dicke: 0.025 m; Höhe: 0.25 m; Programmversion: 3.1; Text3: 0; Plugin_Bezeichnung: MainObject; Plugin_Objektname: SmartPartCompressed; Version: 1.1; Abstand_Öffn_Unten: 3.75 m; ash T_Feuchtebeständigkeit: nein; Feuerwiderstandsklasse~: nein
WV 1.1 | H2 Ebene +1 |  | 1163Sma0814703017 |  | VUK1 - Desinfektionsmittelspender | St | Trockenbauarbeiten | SmartPart | WV 1.1 |  |  |  | 3.75 |  |  |  |  | - | AllplanAttributes - Text1: WA2018; UK: 0 m; OK: 0 m; V6: 0 m; V7: 0 m; V8: 0 m; V9: 0; Länge: 2.08 m; Dicke: 0.025 m; Höhe: 0.25 m; Programmversion: 3.1; Text3: 0; Plugin_Bezeichnung: MainObject; Plugin_Objektname: SmartPartCompressed; Version: 1.1; Abstand_Öffn_Unten: 3.75 m; ash T_Feuchtebeständigkeit: nein; Feuerwiderstandsklasse~: nein
WV 1.1 | H2 Ebene +1 |  | 1163Sma0814703052 |  | VUK1 - Desinfektionsmittelspender | St | Trockenbauarbeiten | SmartPart | WV 1.1 |  |  |  | 3.75 |  |  |  |  | - | AllplanAttributes - Text1: WA2018; UK: 0 m; OK: 0 m; V6: 0 m; V7: 0 m; V8: 0 m; V9: 0; Länge: 0.64 m; Dicke: 0.025 m; Höhe: 0.25 m; Programmversion: 3.1; Text3: 0; Plugin_Bezeichnung: MainObject; Plugin_Objektname: SmartPartCompressed; Version: 1.1; Abstand_Öffn_Unten: 3.75 m; ash T_Feuchtebeständigkeit: nein; Feuerwiderstandsklasse~: nein
WV 1.1 | H2 Ebene +1 |  | 1163Sma0814703110 |  | VUK1 - Desinfektionsmittelspender | St | Trockenbauarbeiten | SmartPart | WV 1.1 |  |  |  | 3.75 |  |  |  |  | - | AllplanAttributes - Text1: WA2018; UK: 0 m; OK: 0 m; V6: 0 m; V7: 0 m; V8: 0 m; V9: 0; Länge: 0.27 m; Dicke: 0.025 m; Höhe: 0.25 m; Programmversion: 3.1; Text3: 0; Plugin_Bezeichnung: MainObject; Plugin_Objektname: SmartPartCompressed; Version: 1.1; Abstand_Öffn_Unten: 3.75 m; ash T_Feuchtebeständigkeit: nein; Feuerwiderstandsklasse~: nein
WV 1.1 | H2 Ebene +1 |  | 1163Sma0814703087 |  | VUK1 - Desinfektionsmittelspender | St | Trockenbauarbeiten | SmartPart | WV 1.1 |  |  |  | 3.75 |  |  |  |  | - | AllplanAttributes - Text1: WA2018; UK: 0 m; OK: 0 m; V6: 0 m; V7: 0 m; V8: 0 m; V9: 0; Länge: 2.98 m; Dicke: 0.025 m; Höhe: 0.25 m; Programmversion: 3.1; Text3: 0; Plugin_Bezeichnung: MainObject; Plugin_Objektname: SmartPartCompressed; Version: 1.1; Abstand_Öffn_Unten: 3.75 m; ash T_Feuchtebeständigkeit: nein; Feuerwiderstandsklasse~: nein
WV 1.1 | H2 Ebene +1 |  | 1163Sma0814702971 |  | VUK1 - Desinfektionsmittelspender | St | Trockenbauarbeiten | SmartPart | WV 1.1 |  |  |  | 3.75 |  |  |  |  | - | AllplanAttributes - Text1: WA2018; UK: 0 m; OK: 0 m; V6: 0 m; V7: 0 m; V8: 0 m; V9: 0; Länge: 3.79 m; Dicke: 0.025 m; Höhe: 0.25 m; Programmversion: 3.1; Text3: 0; Plugin_Bezeichnung: MainObject; Plugin_Objektname: SmartPartCompressed; Version: 1.1; Abstand_Öffn_Unten: 3.75 m; ash T_Feuchtebeständigkeit: nein; Feuerwiderstandsklasse~: nein
WV 1.1 | H2 Ebene +1 |  | 1163Sma0814703741 |  | VUK1 | St | Trockenbauarbeiten | SmartPart | WV 1.1 |  |  |  | 3.75 |  |  |  |  | - | AllplanAttributes - UK: 0 m; OK: 0 m; V6: 0 m; V7: 0 m; V8: 0 m; V9: 0; Länge: 0.2 m; Dicke: 0.025 m; Höhe: 0.4 m; Programmversion: 3.1; Text3: 0; Plugin_Bezeichnung: MainObject; Plugin_Objektname: SmartPartCompressed; Version: 1.1; Abstand_Öffn_Unten: 4.38 m; ash T_Feuchtebeständigkeit: nein; Feuerwiderstandsklasse~: nein
WV 1.1 | H2 Ebene +1 |  | 1163Sma0814703791 |  | VUK1 | St | Trockenbauarbeiten | SmartPart | WV 1.1 |  |  |  | 3.75 |  |  |  |  | - | AllplanAttributes - UK: 0 m; OK: 0 m; V6: 0 m; V7: 0 m; V8: 0 m; V9: 0; Länge: 0.2 m; Dicke: 0.025 m; Höhe: 0.4 m; Programmversion: 3.1; Text3: 0; Plugin_Bezeichnung: MainObject; Plugin_Objektname: SmartPartCompressed; Version: 1.1; Abstand_Öffn_Unten: 4.38 m; ash T_Feuchtebeständigkeit: nein; Feuerwiderstandsklasse~: nein
WV 1.1 | H2 Ebene +1 |  | 1163Sma0814703814 |  | VUK1 | St | Trockenbauarbeiten | SmartPart | WV 1.1 |  |  |  | 3.75 |  |  |  |  | - | AllplanAttributes - UK: 0 m; OK: 0 m; V6: 0 m; V7: 0 m; V8: 0 m; V9: 0; Länge: 0.6 m; Dicke: 0.025 m; Höhe: 0.35 m; Programmversion: 3.1; Text3: 0; Plugin_Bezeichnung: MainObject; Plugin_Objektname: SmartPartCompressed; Version: 1.1; Abstand_Öffn_Unten: 5 m; ash T_Feuchtebeständigkeit: nein; Feuerwiderstandsklasse~: nein
WV 1.1 | H2 Ebene +1 |  | 1163Sma0814703768 |  | VUK1 | St | Trockenbauarbeiten | SmartPart | WV 1.1 |  |  |  | 3.75 |  |  |  |  | - | AllplanAttributes - UK: 0 m; OK: 0 m; V6: 0 m; V7: 0 m; V8: 0 m; V9: 0; Länge: 0.2 m; Dicke: 0.025 m; Höhe: 0.4 m; Programmversion: 3.1; Text3: 0; Plugin_Bezeichnung: MainObject; Plugin_Objektname: SmartPartCompressed; Version: 1.1; Abstand_Öffn_Unten: 4.38 m; ash T_Feuchtebeständigkeit: nein; Feuerwiderstandsklasse~: nein
WV 1.1 | H2 Ebene +1 |  | 1163Sma0814506058 |  | VUK1 - Hängeschrank | St | Trockenbauarbeiten | SmartPart | WV 1.1 |  |  |  | 3.75 |  |  |  |  | - | AllplanAttributes - Text1: WA2018; UK: 0 m; OK: 0 m; V6: 0 m; V7: 0 m; V8: 0 m; V9: 0; Länge: 1.5 m; Dicke: 0.025 m; Höhe: 0.2 m; Programmversion: 3.1; Text3: 0; Plugin_Bezeichnung: MainObject; Plugin_Objektname: SmartPartCompressed; Version: 1.1; Abstand_Öffn_Unten: 6.1 m; ash T_Feuchtebeständigkeit: nein; Feuerwiderstandsklasse~: nein
WV 1.1 | H2 Ebene +1 |  | 1163Sma0814505966 |  | VUK1 - Seifenspender | St | Trockenbauarbeiten | SmartPart | WV 1.1 |  |  |  | 3.75 |  |  |  |  | - | AllplanAttributes - Text1: WA2016; UK: 0 m; OK: 0 m; V6: 0 m; V7: 0 m; V8: 0 m; V9: 0; Länge: 0.15 m; Dicke: 0.025 m; Höhe: 0.3 m; Programmversion: 3.1; Text3: 0; Plugin_Bezeichnung: MainObject; Plugin_Objektname: SmartPartCompressed; Version: 1.1; Abstand_Öffn_Unten: 5.01 m; ash T_Feuchtebeständigkeit: nein; Feuerwiderstandsklasse~: nein
WV 1.1 | H2 Ebene +1 |  | 1163Sma0814705693 |  | VUK5 - Handlauf | St | Trockenbauarbeiten | SmartPart | WV 1.1 |  |  |  | 3.75 |  |  |  |  | - | AllplanAttributes - Text1: WA; UK: 0 m; OK: 0 m; V6: 0 m; V7: 0 m; V8: 0 m; V9: 0; Länge: 1.65 m; Dicke: 0.025 m; Höhe: 0.2 m; Programmversion: 3.1; Text3: 0; Plugin_Bezeichnung: MainObject; Plugin_Objektname: SmartPartCompressed; Version: 1.1; Abstand_Öffn_Unten: 4.65 m; ash T_Feuchtebeständigkeit: nein; Feuerwiderstandsklasse~: nein
 | H2 Ebene +1 | WI-LB | 1163Wa 0814705936 | yes | Codetext | m² | Trockenbauarbeiten | Wand | Innenwand 1-Schalig | WI-LB | 0 | A | 3.75 | 1163HWa0814107885 | NEW |  | no | 0 | 0 | no | 47 | no | Codetext | AllplanAttributes - W_Deckenanschluss: Gleitender Deckenanschluss Fall 01; ash_W_Trockenbau_Qualitäten: 1b; Positionsnummer_Text: U100
 | H2 Ebene +1 | WI-LB | 1163Wa 0814705872 | yes | Codetext | m² | Trockenbauarbeiten | Wand | Innenwand 1-Schalig | WI-LB | 0 | A | 3.75 | 1163HWa0814107885 | NEW | no | no | 0 | 0 | no | 47 | no | Codetext | AllplanAttributes - W_Deckenanschluss: Gleitender Deckenanschluss Fall 01; ash_W_Trockenbau_Qualitäten: 8; Positionsnummer_Text: U100
 | H2 Ebene +1 | WI-LB | 1163Wa 0814705874 | yes | Codetext | m² | Trockenbauarbeiten | Wand | Innenwand 1-Schalig | WI-LB | 0 | A | 3.75 | 1163HWa0814107885 | NEW | no | no | 0 | 0 | no | 47 | no | Codetext | AllplanAttributes - W_Deckenanschluss: Gleitender Deckenanschluss Fall 01; ash_W_Trockenbau_Qualitäten: 8; Positionsnummer_Text: U100
 | H2 Ebene +1 | WI-LB | 1163Wa 0814705893 | yes | Codetext | m² | Trockenbauarbeiten | Wand | Innenwand 1-Schalig | WI-LB | 0 | A | 3.75 | 1163HWa0814107885 | NEW | no | no | 0 | 0 | no | 47 | no | Codetext | AllplanAttributes - W_Deckenanschluss: Gleitender Deckenanschluss Fall 01; ash_W_Trockenbau_Qualitäten: 8; Positionsnummer_Text: U100
 | H2 Ebene +1 | WI-LB | 1163Wa 0814705884 | yes | Codetext | m² | Trockenbauarbeiten | Wand | Innenwand 1-Schalig | WI-LB | 0 | A | 3.75 | 1163HWa0814107885 | NEW | no | no | 0 | 0 | no | 47 | no | Codetext | AllplanAttributes - W_Deckenanschluss: Gleitender Deckenanschluss Fall 01; ash_W_Trockenbau_Qualitäten: 18; Positionsnummer_Text: U100
 | H2 Ebene +1 | WI-LB | 1163Wa 0814705886 | yes | Codetext | m² | Trockenbauarbeiten | Wand | Innenwand 1-Schalig | WI-LB | 0 | A | 3.75 | 1163HWa0814107885 | NEW | no | no | 0 | 0 | no | 47 | no | Codetext | AllplanAttributes - W_Deckenanschluss: Gleitender Deckenanschluss Fall 01; ash_W_Trockenbau_Qualitäten: 18; Positionsnummer_Text: U100
 | H2 Ebene +1 | WI-LB | 1163Wa 0814705951 | yes | Codetext | m² | Trockenbauarbeiten | Wand | Innenwand 1-Schalig | WI-LB | 0 | A | 3.75 | 1163HWa0814107885 | NEW |  | no | 0 | 0 | no | 47 | no | Codetext | AllplanAttributes - W_Deckenanschluss: Gleitender Deckenanschluss Fall 01; ash_W_Trockenbau_Qualitäten: 1a; Positionsnummer_Text: U100
 | H2 Ebene +1 | WI-LB | 1163Wa 0814706000 | yes | Codetext | m² | Trockenbauarbeiten | Wand | Innenwand 1-Schalig | WI-LB | 0 | A | 3.75 | 1163HWa0814107885 | NEW |  | no | 0 | 0 | no | 47 | no | Codetext | AllplanAttributes - W_Deckenanschluss: Gleitender Deckenanschluss Fall 01; ash_W_Trockenbau_Qualitäten: 1b; Positionsnummer_Text: U100
 | H2 Ebene +1 | WI-LB | 1163Wa 0814705997 | yes | Codetext | m² | Trockenbauarbeiten | Wand | Innenwand 1-Schalig | WI-LB | 0 | A | 3.75 | 1163HWa0814107885 | NEW |  | no | 0 | 0 | no | 47 | no | Codetext | AllplanAttributes - W_Deckenanschluss: Gleitender Deckenanschluss Fall 01; ash_W_Trockenbau_Qualitäten: 1b; Positionsnummer_Text: U100
 | H2 Ebene +1 | WI-IW | 1163Wa 0814706396 | yes | Codetext | m² | Trockenbauarbeiten | Wand | Installationswand | WI-IW | 0 | A | 3.75 | 1163HWa0812464233 | NEW |  | no | 0 | 0 | no | 0 | no | Codetext | AllplanAttributes - W_Deckenanschluss: Gleitender Deckenanschluss Fall 01; ash_W_Trockenbau_Qualitäten: 18; Positionsnummer_Text: U100
 | H2 Ebene +1 | Installationsraum | 1163Wa 0814706397 | yes | Codetext | m² | Trockenbauarbeiten | Wand | Installationswand | Installationsraum | 0 | A | 3.75 | 1163HWa0812464233 | NEW |  | no | 0 | 0 | no | 0 | no | Codetext | AllplanAttributes - W_Deckenanschluss: Gleitender Deckenanschluss Fall 01; Positionsnummer_Text: U100
WV 1.1 | H2 Ebene +1 |  | 1163Sma0814506333 |  | VUK1 - Hängeschrank | St | Trockenbauarbeiten | SmartPart | WV 1.1 |  |  |  | 3.75 |  |  |  |  | - | AllplanAttributes - Text1: WA2009; UK: 0 m; OK: 0 m; V6: 0 m; V7: 0 m; V8: 0 m; V9: 0; Länge: 1.25 m; Dicke: 0.025 m; Höhe: 0.2 m; Programmversion: 3.1; Text3: 0; Plugin_Bezeichnung: MainObject; Plugin_Objektname: SmartPartCompressed; Version: 1.1; Abstand_Öffn_Unten: 6.1 m; ash T_Feuchtebeständigkeit: nein; Feuerwiderstandsklasse~: nein
WV 1.1 | H2 Ebene +1 |  | 1163Sma0814506298 |  | VUK1 - Wäschehalter | St | Trockenbauarbeiten | SmartPart | WV 1.1 |  |  |  | 3.75 |  |  |  |  | - | AllplanAttributes - Text1: WA2009; UK: 0 m; OK: 0 m; V6: 0 m; V7: 0 m; V8: 0 m; V9: 0; Länge: 1 m; Dicke: 0.025 m; Höhe: 0.2 m; Programmversion: 3.1; Text3: 0; Plugin_Bezeichnung: MainObject; Plugin_Objektname: SmartPartCompressed; Version: 1.1; Abstand_Öffn_Unten: 5.375 m; ash T_Feuchtebeständigkeit: nein; Feuerwiderstandsklasse~: nein
 | H2 Ebene +1 | WI-STB | 1163Wa 0812544544 | yes | Codetext | m² | Zimmer- und Holzbauarbeiten | Wand | Außenwand 1-Schalig | WI-STB | 0 | A | 3.75 | 1163HWa0812544535 | NEW | yes | no | REI 60-A1 - D,s2-d0 /A1 | 0 | no | 52 | no | Codetext | AllplanAttributes - Positionsnummer_Text: U100
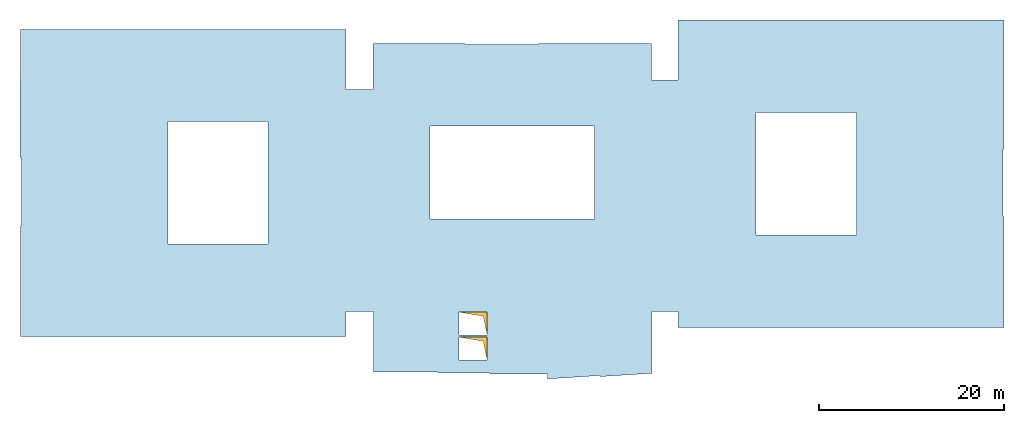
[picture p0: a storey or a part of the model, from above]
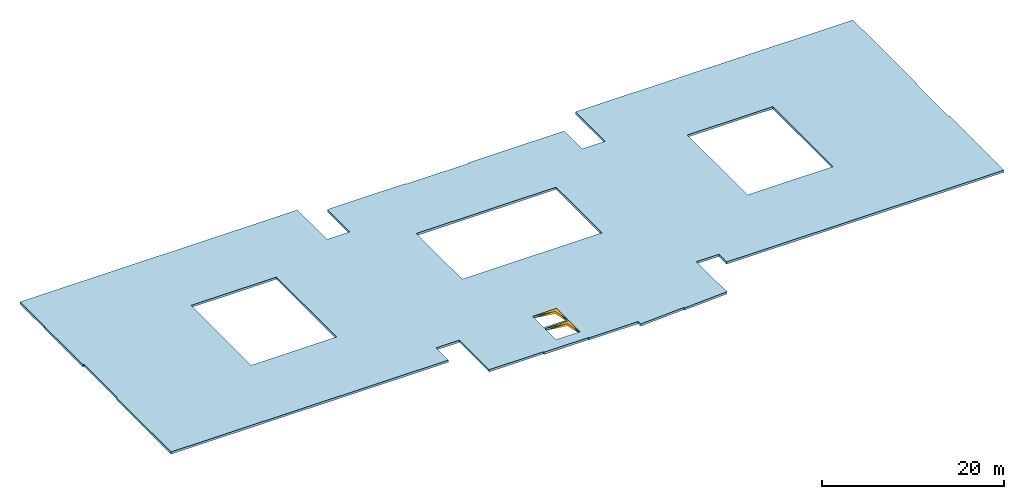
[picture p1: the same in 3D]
Properties of the parts of a building model (IFC4), part 67 of 80

# IfcWall (6826)
Name | In | Material | Allright_Bauteil_ID | 2D Interaktion | Codetext | Abrechnungsart | Gewerk | Objektname | Bezeichnung | AllplanAttributes, Material | Typ = SurfaceSpreadOfFlame | Brandschutzklasse | OKFF | P_ID | Status | LoadBearing | IsExternal | FireRating | ThermalTransmittance (W/K/m2) | Combustible | AcousticRating | Compartmentation | Reference
Promat / BS | H2 Ebene +1 | WI-LB | 1163Wa 0814615229 | yes | Codetext | m² | Trockenbauarbeiten | Wand | Promat / BS | WI-LB | 0 | A | 3.75 | 1163HWa0812835805 | NEW | no | no |  | 0 | no | 0 | no | Codetext | AllplanAttributes - Positionsnummer_Text: U100
Promat / BS | H2 Ebene +1 | WI-LB | 1163Wa 0814615303 | yes | Codetext | m² | Trockenbauarbeiten | Wand | Promat / BS | WI-LB | 0 | A | 3.75 | 1163HWa0812835805 | NEW | no | no |  | 0 | no | 0 | no | Codetext | AllplanAttributes - ash_W_Trockenbau_Qualitäten: 18; Positionsnummer_Text: U100
Promat / BS | H2 Ebene +1 | WI-LB | 1163Wa 0814615292 | yes | Codetext | m² | Trockenbauarbeiten | Wand | Promat / BS | WI-LB | 0 | A | 3.75 | 1163HWa0812835805 | NEW | no | no |  | 0 | no | 0 | no | Codetext | AllplanAttributes - ash_W_Trockenbau_Qualitäten: 18; Positionsnummer_Text: U100
Promat / BS | H2 Ebene +1 | WI-LB | 1163Wa 0814615269 | yes | Codetext | m² | Trockenbauarbeiten | Wand | Promat / BS | WI-LB | 0 | A | 3.75 | 1163HWa0812835805 | NEW | no | no |  | 0 | no | 0 | no | Codetext | AllplanAttributes - ash_W_Trockenbau_Qualitäten: 18; Positionsnummer_Text: U100
Promat / BS | H2 Ebene +1 | WI-LB | 1163Wa 0814615257 | yes | Codetext | m² | Trockenbauarbeiten | Wand | Promat / BS | WI-LB | 0 | A | 3.75 | 1163HWa0812835805 | NEW | no | no |  | 0 | no | 0 | no | Codetext | AllplanAttributes - Positionsnummer_Text: U100
Promat / BS | H2 Ebene +1 | WI-LB | 1163Wa 0814615281 | yes | Codetext | m² | Trockenbauarbeiten | Wand | Promat / BS | WI-LB | 0 | A | 3.75 | 1163HWa0812835805 | NEW | no | no |  | 0 | no | 0 | no | Codetext | AllplanAttributes - ash_W_Trockenbau_Qualitäten: 18; Positionsnummer_Text: U100
Promat / BS | H2 Ebene +1 | WI-LB | 1163Wa 0814615247 | yes | Codetext | m² | Trockenbauarbeiten | Wand | Promat / BS | WI-LB | 0 | A | 3.75 | 1163HWa0812835805 | NEW | no | no |  | 0 | no | 0 | no | Codetext | AllplanAttributes - Positionsnummer_Text: U100
WV 1.1 | H2 Ebene +1 |  | 1163Sma0814506203 |  | VUK1 - Hängeschrank | St | Trockenbauarbeiten | SmartPart | WV 1.1 |  |  |  | 3.75 |  |  |  |  | - | AllplanAttributes - Text1: WA2018; UK: 0 m; OK: 0 m; V6: 0 m; V7: 0 m; V8: 0 m; V9: 0; Länge: 1.5 m; Dicke: 0.025 m; Höhe: 0.2 m; Programmversion: 3.1; Text3: 0; Plugin_Bezeichnung: MainObject; Plugin_Objektname: SmartPartCompressed; Version: 1.1; Abstand_Öffn_Unten: 6.1 m; ash T_Feuchtebeständigkeit: nein; Feuerwiderstandsklasse~: nein
WV 1.1 | H2 Ebene +1 |  | 1163Sma0814506177 |  | VUK1 - Seifenspender | St | Trockenbauarbeiten | SmartPart | WV 1.1 |  |  |  | 3.75 |  |  |  |  | - | AllplanAttributes - Text1: WA2016; UK: 0 m; OK: 0 m; V6: 0 m; V7: 0 m; V8: 0 m; V9: 0; Länge: 0.2 m; Dicke: 0.025 m; Höhe: 0.3 m; Programmversion: 3.1; Text3: 0; Plugin_Bezeichnung: MainObject; Plugin_Objektname: SmartPartCompressed; Version: 1.1; Abstand_Öffn_Unten: 5.01 m; ash T_Feuchtebeständigkeit: nein; Feuerwiderstandsklasse~: nein
WV 1.1 | H2 Ebene +1 |  | 1163Sma0814506179 |  | VUK1 - Desinfektionsmittelspender | St | Trockenbauarbeiten | SmartPart | WV 1.1 |  |  |  | 3.75 |  |  |  |  | - | AllplanAttributes - Text1: WA2016; UK: 0 m; OK: 0 m; V6: 0 m; V7: 0 m; V8: 0 m; V9: 0; Länge: 0.2 m; Dicke: 0.025 m; Höhe: 0.3 m; Programmversion: 3.1; Text3: 0; Plugin_Bezeichnung: MainObject; Plugin_Objektname: SmartPartCompressed; Version: 1.1; Abstand_Öffn_Unten: 5.01 m; ash T_Feuchtebeständigkeit: nein; Feuerwiderstandsklasse~: nein
 | H2 Ebene +1 | WI-LB | 1163Wa 0812446044 | yes | Codetext | m² | Trockenbauarbeiten | Wand | Innenwand 1-Schalig | WI-LB | 0 | A | 3.75 | 1163HWa0812425475 | NEW |  | no | 0 | 0 | no | 47 | no | Codetext | AllplanAttributes - Ortscode_Geschoßbezeichnung: E01; W_Deckenanschluss: Gleitender Deckenanschluss Fall 03; ash_W_Trockenbau_Qualitäten: 1c; Positionsnummer_Text: U100
 | H2 Ebene +1 | WI-HW 60 | 1163Wa 0812441727 | yes | Codetext | m² | Zimmer- und Holzbauarbeiten | Wand | Innenwand 1-Schalig | WI-HW 60 | 0 | A | 3.75 | 1163HWa0812440544 | NEW | no | no | REI 30 | 0 | no | 47 | no | Codetext | AllplanAttributes - ash W_laufende Nr. Statik: 1 (W 1.0/ 1.1/ 1.2); Positionsnummer_Text: U100
 | H2 Ebene +1 | WI-LB | 1163Wa 0813777691 | yes | Codetext | m² | Trockenbauarbeiten | Wand | Innenwand 1-Schalig | WI-LB | 0 | A | 3.75 | 1163HWa0812440544 | NEW | no | no | REI 30-A1 - D,s2-d0 +A1 | 0 | no | 47 | no | Codetext | AllplanAttributes - ash_W_Trockenbau_Qualitäten: 6; Sicherheitsklasse: -; Positionsnummer_Text: U100
 | H2 Ebene +1 | WI-LB | 1163Wa 0813668639 | yes | Codetext | m² | Trockenbauarbeiten | Wand | Innenwand 1-Schalig | WI-LB | 0 | A | 3.75 | 1163HWa0813668638 | NEW |  | no | 0 | 0 | no | 0 | no | Codetext | AllplanAttributes - W_Deckenanschluss: Gleitender Deckenanschluss Fall 01; ash_W_Trockenbau_Qualitäten: 13; Positionsnummer_Text: U100
 | H2 Ebene +1 | WI-HW 60 | 1163Wa 0812443215 | yes | Codetext | m² | Zimmer- und Holzbauarbeiten | Wand | Innenwand 1-Schalig | WI-HW 60 | 0 | A | 3.75 | 1163HWa0812443023 | NEW | no | no | 0 | 0 | no | 47 | no | Codetext | AllplanAttributes - Sicherheitsklasse: -; ash W_laufende Nr. Statik: 3 (W 3.0); Positionsnummer_Text: U100
 | H2 Ebene +1 | WI-LB | 1163Wa 0813776877 | yes | Codetext | m² | Trockenbauarbeiten | Wand | Innenwand 1-Schalig | WI-LB | 0 | A | 3.75 | 1163HWa0812443023 | NEW | no | no | 0 | 0 | no | 47 | no | Codetext | AllplanAttributes - ash_W_Trockenbau_Qualitäten: 6; Sicherheitsklasse: -; Positionsnummer_Text: U100
 | H2 Ebene +1 | WI-LB | 1163Wa 0814723943 | yes | Codetext | m² | Trockenbauarbeiten | Wand | Innenwand 1-Schalig | WI-LB | 0 | A | 3.75 | 1163HWa0812442712 | NEW | no | no | REI 30-A1 - D,s2-d0 +A1 | 0 | no | 47 | no | Codetext | AllplanAttributes - ash_W_Trockenbau_Qualitäten: 8; Sicherheitsklasse: -; Positionsnummer_Text: U100
 | H2 Ebene +1 | Installationsraum | 1163Wa 0814723945 | yes | Codetext | m² | Trockenbauarbeiten | Wand | Innenwand 1-Schalig | Installationsraum | 0 | A | 3.75 | 1163HWa0812442712 | NEW | no | no | 0 | 0 | no | 47 | no | Codetext | AllplanAttributes - Sicherheitsklasse: -; Positionsnummer_Text: U100
 | H2 Ebene +1 | WI-HW 60 | 1163Wa 0814723942 | yes | Codetext | m² | Zimmer- und Holzbauarbeiten | Wand | Innenwand 1-Schalig | WI-HW 60 | 0 | A | 3.75 | 1163HWa0812442712 | NEW | no | no | REI 30-A1 - D,s2-d0 +A1 | 0 | no | 47 | no | Codetext | AllplanAttributes - Sicherheitsklasse: -; ash W_laufende Nr. Statik: 3 (W 3.0); Positionsnummer_Text: U100
 | H2 Ebene +1 | WI-HW 60 | 1163Wa 0814724023 | yes | Codetext | m² | Zimmer- und Holzbauarbeiten | Wand | Innenwand 1-Schalig | WI-HW 60 | 0 | A | 3.75 | 1163HWa0812442712 | NEW | no | no | REI 30-A1 - D,s2-d0 +A1 | 0 | no | 47 | no | Codetext | AllplanAttributes - Sicherheitsklasse: -; ash W_laufende Nr. Statik: 3 (W 3.0); Positionsnummer_Text: U100
 | H2 Ebene +1 | WI-HW 60 | 1163Wa 0812444074 | yes | Codetext | m² | Zimmer- und Holzbauarbeiten | Wand | Innenwand 1-Schalig | WI-HW 60 | 0 | A | 3.75 | 1163HWa0812443050 | NEW | no | no | 0 | 0 | no | 47 | no | Codetext | AllplanAttributes - Sicherheitsklasse: -; ash W_laufende Nr. Statik: 3 (W 3.0); Positionsnummer_Text: U100
 | H2 Ebene +1 | WI-LB | 1163Wa 0813776686 | yes | Codetext | m² | Trockenbauarbeiten | Wand | Innenwand 1-Schalig | WI-LB | 0 | A | 3.75 | 1163HWa0812443050 | NEW | no | no | 0 | 0 | no | 47 | no | Codetext | AllplanAttributes - ash_W_Trockenbau_Qualitäten: 6; Sicherheitsklasse: -; Positionsnummer_Text: U100
 | H2 Ebene +1 | WI-IW | 1163Wa 0813672499 | yes | Codetext | m² | Trockenbauarbeiten | Wand | Installationswand | WI-IW | 0 | A | 3.75 | 1163HWa0813672498 | NEW |  | no | 0 | 0 | no | 47 | no | Codetext | AllplanAttributes - W_Deckenanschluss: Gleitender Deckenanschluss Fall 01; ash_W_Trockenbau_Qualitäten: 19; Positionsnummer_Text: U100
 | H2 Ebene +1 | WI-LB | 1163Wa 0814566219 | yes | Codetext | m² | Trockenbauarbeiten | Wand | Innenwand 1-Schalig | WI-LB | 0 | A | 3.75 | 1163HWa0812442712 | NEW | no | no | REI 30-A1 - D,s2-d0 +A1 | 0 | no | 47 | no | Codetext | AllplanAttributes - ash_W_Trockenbau_Qualitäten: 8; Sicherheitsklasse: -; Positionsnummer_Text: U100
 | H2 Ebene +1 | Installationsraum | 1163Wa 0814566221 | yes | Codetext | m² | Trockenbauarbeiten | Wand | Innenwand 1-Schalig | Installationsraum | 0 | A | 3.75 | 1163HWa0812442712 | NEW | no | no | 0 | 0 | no | 47 | no | Codetext | AllplanAttributes - Sicherheitsklasse: -; Positionsnummer_Text: U100
 | H2 Ebene +1 | WI-HW 60 | 1163Wa 0814566218 | yes | Codetext | m² | Zimmer- und Holzbauarbeiten | Wand | Innenwand 1-Schalig | WI-HW 60 | 0 | A | 3.75 | 1163HWa0812442712 | NEW | no | no | REI 30-A1 - D,s2-d0 +A1 | 0 | no | 47 | no | Codetext | AllplanAttributes - Sicherheitsklasse: -; ash W_laufende Nr. Statik: 3 (W 3.0); Positionsnummer_Text: U100
 | H2 Ebene +1 | WI-LB | 1163Wa 0812443678 | yes | Codetext | m² | Trockenbauarbeiten | Wand | Innenwand 1-Schalig | WI-LB | 0 | A | 3.75 | 1163HWa0812443477 | NEW | no | no | REI 60-A1 - D,s2-d0 /A1 | 0 | no | 0 | no | Codetext | AllplanAttributes - Ortscode_Geschoßbezeichnung: E01; W_Deckenanschluss: Gleitender Deckenanschluss Fall 01; ash_W_Trockenbau_Qualitäten: 1b; Positionsnummer_Text: U100
 | H2 Ebene +1 | WI-LB | 1163Wa 0814511208 | yes | Codetext | m² | Trockenbauarbeiten | Wand | Innenwand 1-Schalig | WI-LB | 0 | A | 3.75 | 1163HWa0812839978 | NEW | no | no | REI 60-A1 - D,s2-d0 /A1 | 0 | no |  | no | Codetext | AllplanAttributes - ash_W_Trockenbau_Qualitäten: 9; Positionsnummer_Text: U100
 | H2 Ebene +1 | WI-LB | 1163Wa 0814593622 | yes | Codetext | m² | Trockenbauarbeiten | Wand | Innenwand 1-Schalig | WI-LB | 0 | A | 3.75 | 1163HWa0812428824 | NEW |  | no | 0 | 0 | no |  | no | Codetext | AllplanAttributes - W_Deckenanschluss: Gleitender Deckenanschluss Fall 01; ash_W_Trockenbau_Qualitäten: 18; Positionsnummer_Text: U100
 | H2 Ebene +1 | WI-LB | 1163Wa 0812446956 | yes | Codetext | m² | Trockenbauarbeiten | Wand | Innenwand 1-Schalig | WI-LB | 0 | A | 3.75 | 1163HWa0812434668 | NEW |  | no | REI 60-A1 - D,s2-d0 +A1 | 0 | no | 52 | no | Codetext | AllplanAttributes - Ortscode_Geschoßbezeichnung: E01; W_Deckenanschluss: Gleitender Deckenanschluss Fall 01; ash_W_Trockenbau_Qualitäten: 4; Positionsnummer_Text: U100
 | H2 Ebene +1 | WI-LB | 1163Wa 0814612136 | yes | Codetext | m² | Trockenbauarbeiten | Wand | Innenwand 1-Schalig | WI-LB | 0 | A | 3.75 | 1163HWa0812434427 | NEW | no | no | REI 60-A1 - D,s2-d0 /A1 | 0 | no | 52 | no | Codetext | AllplanAttributes - ash_W_Trockenbau_Qualitäten: 6; Positionsnummer_Text: U100
 | H2 Ebene +1 | Installationsraum | 1163Wa 0814612135 | yes | Codetext | m² | Trockenbauarbeiten | Wand | Innenwand 1-Schalig | Installationsraum | 0 | A | 3.75 | 1163HWa0812434427 | NEW | no | no | 0 | 0 | no | 52 | no | Codetext | AllplanAttributes - Positionsnummer_Text: U100
 | H2 Ebene +1 | WI-HW 60 | 1163Wa 0814612134 | yes | Codetext | m² | Zimmer- und Holzbauarbeiten | Wand | Innenwand 1-Schalig | WI-HW 60 | 0 | A | 3.75 | 1163HWa0812434427 | NEW | no | no | REI 60-A1 - D,s2-d0 +A1 | 0 | no | 52 | no | Codetext | AllplanAttributes - ash W_laufende Nr. Statik: 3 (W 3.0); Positionsnummer_Text: U100
 | H2 Ebene +1 | WI-LB | 1163Wa 0812494625 | yes | Codetext | m² | Trockenbauarbeiten | Wand | Innenwand 1-Schalig | WI-LB | 0 | A | 3.75 | 1163HWa0812494623 | NEW | no | no | REI 60-A1 - D,s2-d0 +A1 | 0 | no | 0 | no | Codetext | AllplanAttributes - Ortscode_Geschoßbezeichnung: E01; W_Deckenanschluss: Gleitender Deckenanschluss Fall 01; ash_W_Trockenbau_Qualitäten: 1b; Positionsnummer_Text: U100
 | H2 Ebene +1 | WI-IW | 1163Wa 0812467431 | yes | Codetext | m² | Trockenbauarbeiten | Wand | Installationswand | WI-IW | 0 | A | 3.75 | 1163HWa0812467422 | NEW | no | no | 0 | 0 | no | 0 | no | Codetext | AllplanAttributes - W_Deckenanschluss: Gleitender Deckenanschluss Fall 03; ash_W_Trockenbau_Qualitäten: 2; Positionsnummer_Text: U100
 | H2 Ebene +1 | Installationsraum | 1163Wa 0812467430 | yes | Codetext | m² | Trockenbauarbeiten | Wand | Installationswand | Installationsraum | 0 | A | 3.75 | 1163HWa0812467422 | NEW | no | no | 0 | 0 | no | 0 | no | Codetext | AllplanAttributes - Positionsnummer_Text: U100
 | H2 Ebene +1 | WI-IW | 1163Wa 0812467432 | yes | Codetext | m² | Trockenbauarbeiten | Wand | Installationswand | WI-IW | 0 | A | 3.75 | 1163HWa0812467424 | NEW | no | no | 0 | 0 | no | 47 | no | Codetext | AllplanAttributes - W_Deckenanschluss: Gleitender Deckenanschluss Fall 03; ash_W_Trockenbau_Qualitäten: 11; Positionsnummer_Text: U100
 | H2 Ebene +1 | Installationsraum | 1163Wa 0812467439 | yes | Codetext | m² | Trockenbauarbeiten | Wand | Installationswand | Installationsraum | 0 | A | 3.75 | 1163HWa0812467424 | NEW | no | no | 0 | 0 | no | 0 | no | Codetext | AllplanAttributes - Positionsnummer_Text: U100
 | H2 Ebene +1 | WI-IW | 1163Wa 0812467438 | yes | Codetext | m² | Trockenbauarbeiten | Wand | Installationswand | WI-IW | 0 | A | 3.75 | 1163HWa0812467424 | NEW | no | no | 0 | 0 | no | 47 | no | Codetext | AllplanAttributes - W_Deckenanschluss: Gleitender Deckenanschluss Fall 03; ash_W_Trockenbau_Qualitäten: 11; Positionsnummer_Text: U100
 | H2 Ebene +1 | WI-IW | 1163Wa 0812467437 | yes | Codetext | m² | Trockenbauarbeiten | Wand | Installationswand | WI-IW | 0 | A | 3.75 | 1163HWa0812467422 | NEW | no | no | 0 | 0 | no | 0 | no | Codetext | AllplanAttributes - W_Deckenanschluss: Gleitender Deckenanschluss Fall 03; ash_W_Trockenbau_Qualitäten: 2; Positionsnummer_Text: U100
 | H2 Ebene +1 | Installationsraum | 1163Wa 0812467436 | yes | Codetext | m² | Trockenbauarbeiten | Wand | Installationswand | Installationsraum | 0 | A | 3.75 | 1163HWa0812467422 | NEW | no | no | 0 | 0 | no | 0 | no | Codetext | AllplanAttributes - Positionsnummer_Text: U100
 | H2 Ebene +1 | WI-IW | 1163Wa 0812467454 | yes | Codetext | m² | Trockenbauarbeiten | Wand | Installationswand | WI-IW | 0 | A | 3.75 | 1163HWa0812467422 | NEW | no | no | 0 | 0 | no | 0 | no | Codetext | AllplanAttributes - W_Deckenanschluss: Gleitender Deckenanschluss Fall 03; ash_W_Trockenbau_Qualitäten: 2; Positionsnummer_Text: U100
 | H2 Ebene +1 | Installationsraum | 1163Wa 0812467453 | yes | Codetext | m² | Trockenbauarbeiten | Wand | Installationswand | Installationsraum | 0 | A | 3.75 | 1163HWa0812467422 | NEW | no | no | 0 | 0 | no | 0 | no | Codetext | AllplanAttributes - Positionsnummer_Text: U100
 | H2 Ebene +1 | WI-IW | 1163Wa 0812467455 | yes | Codetext | m² | Trockenbauarbeiten | Wand | Installationswand | WI-IW | 0 | A | 3.75 | 1163HWa0812467424 | NEW | no | no | 0 | 0 | no | 47 | no | Codetext | AllplanAttributes - W_Deckenanschluss: Gleitender Deckenanschluss Fall 03; ash_W_Trockenbau_Qualitäten: 11; Positionsnummer_Text: U100
 | H2 Ebene +1 | Installationsraum | 1163Wa 0812467457 | yes | Codetext | m² | Trockenbauarbeiten | Wand | Installationswand | Installationsraum | 0 | A | 3.75 | 1163HWa0812467424 | NEW | no | no | 0 | 0 | no | 0 | no | Codetext | AllplanAttributes - Positionsnummer_Text: U100
 | H2 Ebene +1 | WI-IW | 1163Wa 0812467456 | yes | Codetext | m² | Trockenbauarbeiten | Wand | Installationswand | WI-IW | 0 | A | 3.75 | 1163HWa0812467424 | NEW | no | no | 0 | 0 | no | 47 | no | Codetext | AllplanAttributes - W_Deckenanschluss: Gleitender Deckenanschluss Fall 03; ash_W_Trockenbau_Qualitäten: 11; Positionsnummer_Text: U100
 | H2 Ebene +1 | WI-IW | 1163Wa 0812467447 | yes | Codetext | m² | Trockenbauarbeiten | Wand | Installationswand | WI-IW | 0 | A | 3.75 | 1163HWa0812467422 | NEW | no | no | 0 | 0 | no | 0 | no | Codetext | AllplanAttributes - W_Deckenanschluss: Gleitender Deckenanschluss Fall 03; ash_W_Trockenbau_Qualitäten: 2; Positionsnummer_Text: U100
 | H2 Ebene +1 | Installationsraum | 1163Wa 0812467448 | yes | Codetext | m² | Trockenbauarbeiten | Wand | Installationswand | Installationsraum | 0 | A | 3.75 | 1163HWa0812467422 | NEW | no | no | 0 | 0 | no | 0 | no | Codetext | AllplanAttributes - Positionsnummer_Text: U100
 | H2 Ebene +1 | WI-IW | 1163Wa 0812467628 | yes | Codetext | m² | Trockenbauarbeiten | Wand | Installationswand | WI-IW | 0 | A | 3.75 | 1163HWa0812467422 | NEW | no | no | 0 | 0 | no | 0 | no | Codetext | AllplanAttributes - W_Deckenanschluss: Gleitender Deckenanschluss Fall 03; ash_W_Trockenbau_Qualitäten: 2; Positionsnummer_Text: U100
 | H2 Ebene +1 | Installationsraum | 1163Wa 0812467627 | yes | Codetext | m² | Trockenbauarbeiten | Wand | Installationswand | Installationsraum | 0 | A | 3.75 | 1163HWa0812467422 | NEW | no | no | 0 | 0 | no | 0 | no | Codetext | AllplanAttributes - Positionsnummer_Text: U100
 | H2 Ebene +1 | WI-IW | 1163Wa 0812467466 | yes | Codetext | m² | Trockenbauarbeiten | Wand | Installationswand | WI-IW | 0 | A | 3.75 | 1163HWa0812467424 | NEW | no | no | 0 | 0 | no | 47 | no | Codetext | AllplanAttributes - W_Deckenanschluss: Gleitender Deckenanschluss Fall 03; ash_W_Trockenbau_Qualitäten: 11; Positionsnummer_Text: U100
 | H2 Ebene +1 | Installationsraum | 1163Wa 0812467468 | yes | Codetext | m² | Trockenbauarbeiten | Wand | Installationswand | Installationsraum | 0 | A | 3.75 | 1163HWa0812467424 | NEW | no | no | 0 | 0 | no | 0 | no | Codetext | AllplanAttributes - Positionsnummer_Text: U100
 | H2 Ebene +1 | WI-IW | 1163Wa 0812467467 | yes | Codetext | m² | Trockenbauarbeiten | Wand | Installationswand | WI-IW | 0 | A | 3.75 | 1163HWa0812467424 | NEW | no | no | 0 | 0 | no | 47 | no | Codetext | AllplanAttributes - W_Deckenanschluss: Gleitender Deckenanschluss Fall 03; ash_W_Trockenbau_Qualitäten: 11; Positionsnummer_Text: U100
 | H2 Ebene +1 | WI-IW | 1163Wa 0812467465 | yes | Codetext | m² | Trockenbauarbeiten | Wand | Installationswand | WI-IW | 0 | A | 3.75 | 1163HWa0812467422 | NEW | no | no | 0 | 0 | no | 0 | no | Codetext | AllplanAttributes - W_Deckenanschluss: Gleitender Deckenanschluss Fall 03; ash_W_Trockenbau_Qualitäten: 2; Positionsnummer_Text: U100
 | H2 Ebene +1 | Installationsraum | 1163Wa 0812467464 | yes | Codetext | m² | Trockenbauarbeiten | Wand | Installationswand | Installationsraum | 0 | A | 3.75 | 1163HWa0812467422 | NEW | no | no | 0 | 0 | no | 0 | no | Codetext | AllplanAttributes - Positionsnummer_Text: U100
 | H2 Ebene +1 | WI-IW | 1163Wa 0812441864 | yes | Codetext | m² | Trockenbauarbeiten | Wand | Installationswand | WI-IW | 0 | A | 3.75 | 1163HWa0812441856 | NEW | no | no | 0 | 0 | no | 0 | no | Codetext | AllplanAttributes - W_Deckenanschluss: Gleitender Deckenanschluss Fall 03; ash_W_Trockenbau_Qualitäten: 2; Positionsnummer_Text: U100
 | H2 Ebene +1 | Installationsraum | 1163Wa 0812442497 | yes | Codetext | m² | Trockenbauarbeiten | Wand | Installationswand | Installationsraum | 0 | A | 3.75 | 1163HWa0812441856 | NEW | no | no | 0 | 0 | no | 0 | no | Codetext | AllplanAttributes - Positionsnummer_Text: U100
 | H2 Ebene +1 | WI-IW | 1163Wa 0812441866 | yes | Codetext | m² | Trockenbauarbeiten | Wand | Installationswand | WI-IW | 0 | A | 3.75 | 1163HWa0812441858 | NEW | no | no | 0 | 0 | no | 0 | no | Codetext | AllplanAttributes - W_Deckenanschluss: Gleitender Deckenanschluss Fall 03; ash_W_Trockenbau_Qualitäten: 2; Positionsnummer_Text: U100
 | H2 Ebene +1 | Installationsraum | 1163Wa 0812442495 | yes | Codetext | m² | Trockenbauarbeiten | Wand | Installationswand | Installationsraum | 0 | A | 3.75 | 1163HWa0812441858 | NEW | no | no | 0 | 0 | no | 0 | no | Codetext | AllplanAttributes - Positionsnummer_Text: U100
 | H2 Ebene +1 | WI-IW | 1163Wa 0812446011 | yes | Codetext | m² | Trockenbauarbeiten | Wand | Installationswand | WI-IW | 0 | A | 3.75 | 1163HWa0812467422 | NEW | no | no | 0 | 0 | no | 0 | no | Codetext | AllplanAttributes - W_Deckenanschluss: Gleitender Deckenanschluss Fall 03; ash_W_Trockenbau_Qualitäten: 2; Positionsnummer_Text: U100
 | H2 Ebene +1 | Installationsraum | 1163Wa 0812446155 | yes | Codetext | m² | Trockenbauarbeiten | Wand | Installationswand | Installationsraum | 0 | A | 3.75 | 1163HWa0812467422 | NEW | no | no | 0 | 0 | no | 0 | no | Codetext | AllplanAttributes - Positionsnummer_Text: U100
 | H2 Ebene +1 | WI-IW | 1163Wa 0812446019 | yes | Codetext | m² | Trockenbauarbeiten | Wand | Installationswand | WI-IW | 0 | A | 3.75 | 1163HWa0812467424 | NEW | no | no | 0 | 0 | no | 47 | no | Codetext | AllplanAttributes - W_Deckenanschluss: Gleitender Deckenanschluss Fall 03; ash_W_Trockenbau_Qualitäten: 11; Positionsnummer_Text: U100
 | H2 Ebene +1 | Installationsraum | 1163Wa 0812446021 | yes | Codetext | m² | Trockenbauarbeiten | Wand | Installationswand | Installationsraum | 0 | A | 3.75 | 1163HWa0812467424 | NEW | no | no | 0 | 0 | no | 0 | no | Codetext | AllplanAttributes - Positionsnummer_Text: U100
 | H2 Ebene +1 | WI-IW | 1163Wa 0812446031 | yes | Codetext | m² | Trockenbauarbeiten | Wand | Installationswand | WI-IW | 0 | A | 3.75 | 1163HWa0812467424 | NEW | no | no | 0 | 0 | no | 47 | no | Codetext | AllplanAttributes - W_Deckenanschluss: Gleitender Deckenanschluss Fall 03; ash_W_Trockenbau_Qualitäten: 11; Positionsnummer_Text: U100
 | H2 Ebene +1 | WI-IW | 1163Wa 0812446013 | yes | Codetext | m² | Trockenbauarbeiten | Wand | Installationswand | WI-IW | 0 | A | 3.75 | 1163HWa0812467422 | NEW | no | no | 0 | 0 | no | 0 | no | Codetext | AllplanAttributes - W_Deckenanschluss: Gleitender Deckenanschluss Fall 03; ash_W_Trockenbau_Qualitäten: 2; Positionsnummer_Text: U100
 | H2 Ebene +1 | Installationsraum | 1163Wa 0812446153 | yes | Codetext | m² | Trockenbauarbeiten | Wand | Installationswand | Installationsraum | 0 | A | 3.75 | 1163HWa0812467422 | NEW | no | no | 0 | 0 | no | 0 | no | Codetext | AllplanAttributes - Positionsnummer_Text: U100
 | H2 Ebene +1 | WI-IW | 1163Wa 0812466556 | yes | Codetext | m² | Trockenbauarbeiten | Wand | Installationswand | WI-IW | 0 | A | 3.75 | 1163HWa0812467422 | NEW | no | no | 0 | 0 | no | 0 | no | Codetext | AllplanAttributes - W_Deckenanschluss: Gleitender Deckenanschluss Fall 03; ash_W_Trockenbau_Qualitäten: 2; Positionsnummer_Text: U100
 | H2 Ebene +1 | Installationsraum | 1163Wa 0812466555 | yes | Codetext | m² | Trockenbauarbeiten | Wand | Installationswand | Installationsraum | 0 | A | 3.75 | 1163HWa0812467422 | NEW | no | no | 0 | 0 | no | 0 | no | Codetext | AllplanAttributes - Positionsnummer_Text: U100
 | H2 Ebene +1 | WI-IW | 1163Wa 0812466557 | yes | Codetext | m² | Trockenbauarbeiten | Wand | Installationswand | WI-IW | 0 | A | 3.75 | 1163HWa0812467424 | NEW | no | no | 0 | 0 | no | 47 | no | Codetext | AllplanAttributes - W_Deckenanschluss: Gleitender Deckenanschluss Fall 03; ash_W_Trockenbau_Qualitäten: 11; Positionsnummer_Text: U100
 | H2 Ebene +1 | Installationsraum | 1163Wa 0812466564 | yes | Codetext | m² | Trockenbauarbeiten | Wand | Installationswand | Installationsraum | 0 | A | 3.75 | 1163HWa0812467424 | NEW | no | no | 0 | 0 | no | 0 | no | Codetext | AllplanAttributes - Positionsnummer_Text: U100
 | H2 Ebene +1 | WI-IW | 1163Wa 0812466563 | yes | Codetext | m² | Trockenbauarbeiten | Wand | Installationswand | WI-IW | 0 | A | 3.75 | 1163HWa0812467424 | NEW | no | no | 0 | 0 | no | 47 | no | Codetext | AllplanAttributes - W_Deckenanschluss: Gleitender Deckenanschluss Fall 03; ash_W_Trockenbau_Qualitäten: 11; Positionsnummer_Text: U100
 | H2 Ebene +1 | WI-IW | 1163Wa 0812466562 | yes | Codetext | m² | Trockenbauarbeiten | Wand | Installationswand | WI-IW | 0 | A | 3.75 | 1163HWa0812467422 | NEW | no | no | 0 | 0 | no | 0 | no | Codetext | AllplanAttributes - W_Deckenanschluss: Gleitender Deckenanschluss Fall 03; ash_W_Trockenbau_Qualitäten: 2; Positionsnummer_Text: U100
 | H2 Ebene +1 | Installationsraum | 1163Wa 0812466561 | yes | Codetext | m² | Trockenbauarbeiten | Wand | Installationswand | Installationsraum | 0 | A | 3.75 | 1163HWa0812467422 | NEW | no | no | 0 | 0 | no | 0 | no | Codetext | AllplanAttributes - Positionsnummer_Text: U100
 | H2 Ebene +1 | WI-IW | 1163Wa 0812467660 | yes | Codetext | m² | Trockenbauarbeiten | Wand | Installationswand | WI-IW | 0 | A | 3.75 | 1163HWa0812467422 | NEW | no | no | 0 | 0 | no | 0 | no | Codetext | AllplanAttributes - W_Deckenanschluss: Gleitender Deckenanschluss Fall 03; ash_W_Trockenbau_Qualitäten: 2; Positionsnummer_Text: U100
 | H2 Ebene +1 | Installationsraum | 1163Wa 0812467661 | yes | Codetext | m² | Trockenbauarbeiten | Wand | Installationswand | Installationsraum | 0 | A | 3.75 | 1163HWa0812467422 | NEW | no | no | 0 | 0 | no | 0 | no | Codetext | AllplanAttributes - Positionsnummer_Text: U100
 | H2 Ebene +1 | WI-IW | 1163Wa 0812466687 | yes | Codetext | m² | Trockenbauarbeiten | Wand | Installationswand | WI-IW | 0 | A | 3.75 | 1163HWa0812467424 | NEW | no | no | 0 | 0 | no | 47 | no | Codetext | AllplanAttributes - W_Deckenanschluss: Gleitender Deckenanschluss Fall 03; ash_W_Trockenbau_Qualitäten: 11; Positionsnummer_Text: U100
 | H2 Ebene +1 | Installationsraum | 1163Wa 0812466689 | yes | Codetext | m² | Trockenbauarbeiten | Wand | Installationswand | Installationsraum | 0 | A | 3.75 | 1163HWa0812467424 | NEW | no | no | 0 | 0 | no | 0 | no | Codetext | AllplanAttributes - Positionsnummer_Text: U100
 | H2 Ebene +1 | WI-IW | 1163Wa 0812466688 | yes | Codetext | m² | Trockenbauarbeiten | Wand | Installationswand | WI-IW | 0 | A | 3.75 | 1163HWa0812467424 | NEW | no | no | 0 | 0 | no | 47 | no | Codetext | AllplanAttributes - W_Deckenanschluss: Gleitender Deckenanschluss Fall 03; ash_W_Trockenbau_Qualitäten: 11; Positionsnummer_Text: U100
 | H2 Ebene +1 | WI-IW | 1163Wa 0812466685 | yes | Codetext | m² | Trockenbauarbeiten | Wand | Installationswand | WI-IW | 0 | A | 3.75 | 1163HWa0812467422 | NEW | no | no | 0 | 0 | no | 0 | no | Codetext | AllplanAttributes - W_Deckenanschluss: Gleitender Deckenanschluss Fall 03; ash_W_Trockenbau_Qualitäten: 2; Positionsnummer_Text: U100
 | H2 Ebene +1 | Installationsraum | 1163Wa 0812466686 | yes | Codetext | m² | Trockenbauarbeiten | Wand | Installationswand | Installationsraum | 0 | A | 3.75 | 1163HWa0812467422 | NEW | no | no | 0 | 0 | no | 0 | no | Codetext | AllplanAttributes - Positionsnummer_Text: U100
 | H2 Ebene +1 | Installationsraum | 1163Wa 0812446749 | yes | Codetext | m² | Trockenbauarbeiten | Wand | Installationswand | Installationsraum | 0 | A | 3.75 | 1163HWa0812467422 | NEW | no | no | 0 | 0 | no | 0 | no | Codetext | AllplanAttributes - Positionsnummer_Text: U100
 | H2 Ebene +1 | WI-IW | 1163Wa 0812446751 | yes | Codetext | m² | Trockenbauarbeiten | Wand | Installationswand | WI-IW | 0 | A | 3.75 | 1163HWa0812467422 | NEW | no | no | 0 | 0 | no | 0 | no | Codetext | AllplanAttributes - W_Deckenanschluss: Gleitender Deckenanschluss Fall 03; ash_W_Trockenbau_Qualitäten: 2; Positionsnummer_Text: U100
 | H2 Ebene +1 | Installationsraum | 1163Wa 0814661424 | yes | Codetext | m² | Trockenbauarbeiten | Wand | Installationswand | Installationsraum | 0 | A | 3.75 | 1163HWa0812838160 | NEW | no | no | 0 | 0 | no | 0 | no | Codetext | AllplanAttributes - Positionsnummer_Text: U100
 | H2 Ebene +1 | WI-VS | 1163Wa 0814661425 | yes | Codetext | m² | Trockenbauarbeiten | Wand | Installationswand | WI-VS | 0 | A | 3.75 | 1163HWa0812838160 | NEW | no | no | 0 | 0 | no | 0 | no | Codetext | AllplanAttributes - W_Deckenanschluss: Gleitender Deckenanschluss Fall 03; ash_W_Trockenbau_Qualitäten: 2; Positionsnummer_Text: U100
 | H2 Ebene +1 | WI-IW | 1163Wa 0812467961 | yes | Codetext | m² | Trockenbauarbeiten | Wand | Installationswand | WI-IW | 0 | A | 3.75 | 1163HWa0812467422 | NEW | no | no | 0 | 0 | no | 0 | no | Codetext | AllplanAttributes - W_Deckenanschluss: Gleitender Deckenanschluss Fall 03; ash_W_Trockenbau_Qualitäten: 2; Positionsnummer_Text: U100
 | H2 Ebene +1 | Installationsraum | 1163Wa 0812467960 | yes | Codetext | m² | Trockenbauarbeiten | Wand | Installationswand | Installationsraum | 0 | A | 3.75 | 1163HWa0812467422 | NEW | no | no | 0 | 0 | no | 0 | no | Codetext | AllplanAttributes - Positionsnummer_Text: U100
 | H2 Ebene +1 | WI-IW | 1163Wa 0812467962 | yes | Codetext | m² | Trockenbauarbeiten | Wand | Installationswand | WI-IW | 0 | A | 3.75 | 1163HWa0812467424 | NEW | no | no | 0 | 0 | no | 47 | no | Codetext | AllplanAttributes - W_Deckenanschluss: Gleitender Deckenanschluss Fall 03; ash_W_Trockenbau_Qualitäten: 11; Positionsnummer_Text: U100
 | H2 Ebene +1 | Installationsraum | 1163Wa 0812467969 | yes | Codetext | m² | Trockenbauarbeiten | Wand | Installationswand | Installationsraum | 0 | A | 3.75 | 1163HWa0812467424 | NEW | no | no | 0 | 0 | no | 0 | no | Codetext | AllplanAttributes - Positionsnummer_Text: U100
 | H2 Ebene +1 | WI-IW | 1163Wa 0812467968 | yes | Codetext | m² | Trockenbauarbeiten | Wand | Installationswand | WI-IW | 0 | A | 3.75 | 1163HWa0812467424 | NEW | no | no | 0 | 0 | no | 47 | no | Codetext | AllplanAttributes - W_Deckenanschluss: Gleitender Deckenanschluss Fall 03; ash_W_Trockenbau_Qualitäten: 11; Positionsnummer_Text: U100
 | H2 Ebene +1 | WI-IW | 1163Wa 0812467967 | yes | Codetext | m² | Trockenbauarbeiten | Wand | Installationswand | WI-IW | 0 | A | 3.75 | 1163HWa0812467422 | NEW | no | no | 0 | 0 | no | 0 | no | Codetext | AllplanAttributes - W_Deckenanschluss: Gleitender Deckenanschluss Fall 03; ash_W_Trockenbau_Qualitäten: 2; Positionsnummer_Text: U100
 | H2 Ebene +1 | Installationsraum | 1163Wa 0812467966 | yes | Codetext | m² | Trockenbauarbeiten | Wand | Installationswand | Installationsraum | 0 | A | 3.75 | 1163HWa0812467422 | NEW | no | no | 0 | 0 | no | 0 | no | Codetext | AllplanAttributes - Positionsnummer_Text: U100
 | H2 Ebene +1 | WI-IW | 1163Wa 0812468205 | yes | Codetext | m² | Trockenbauarbeiten | Wand | Installationswand | WI-IW | 0 | A | 3.75 | 1163HWa0812467422 | NEW | no | no | 0 | 0 | no | 0 | no | Codetext | AllplanAttributes - W_Deckenanschluss: Gleitender Deckenanschluss Fall 03; ash_W_Trockenbau_Qualitäten: 2; Positionsnummer_Text: U100
 | H2 Ebene +1 | Installationsraum | 1163Wa 0812468206 | yes | Codetext | m² | Trockenbauarbeiten | Wand | Installationswand | Installationsraum | 0 | A | 3.75 | 1163HWa0812467422 | NEW | no | no | 0 | 0 | no | 0 | no | Codetext | AllplanAttributes - Positionsnummer_Text: U100
 | H2 Ebene +1 | WI-IW | 1163Wa 0812468204 | yes | Codetext | m² | Trockenbauarbeiten | Wand | Installationswand | WI-IW | 0 | A | 3.75 | 1163HWa0812467424 | NEW | no | no | 0 | 0 | no | 47 | no | Codetext | AllplanAttributes - W_Deckenanschluss: Gleitender Deckenanschluss Fall 03; ash_W_Trockenbau_Qualitäten: 11; Positionsnummer_Text: U100
 | H2 Ebene +1 | Installationsraum | 1163Wa 0812468200 | yes | Codetext | m² | Trockenbauarbeiten | Wand | Installationswand | Installationsraum | 0 | A | 3.75 | 1163HWa0812467424 | NEW | no | no | 0 | 0 | no | 0 | no | Codetext | AllplanAttributes - Positionsnummer_Text: U100
 | H2 Ebene +1 | WI-IW | 1163Wa 0812468201 | yes | Codetext | m² | Trockenbauarbeiten | Wand | Installationswand | WI-IW | 0 | A | 3.75 | 1163HWa0812467424 | NEW | no | no | 0 | 0 | no | 47 | no | Codetext | AllplanAttributes - W_Deckenanschluss: Gleitender Deckenanschluss Fall 03; ash_W_Trockenbau_Qualitäten: 11; Positionsnummer_Text: U100
 | H2 Ebene +1 | WI-IW | 1163Wa 0812468202 | yes | Codetext | m² | Trockenbauarbeiten | Wand | Installationswand | WI-IW | 0 | A | 3.75 | 1163HWa0812467422 | NEW | no | no | 0 | 0 | no | 0 | no | Codetext | AllplanAttributes - W_Deckenanschluss: Gleitender Deckenanschluss Fall 03; ash_W_Trockenbau_Qualitäten: 2; Positionsnummer_Text: U100
 | H2 Ebene +1 | Installationsraum | 1163Wa 0812468203 | yes | Codetext | m² | Trockenbauarbeiten | Wand | Installationswand | Installationsraum | 0 | A | 3.75 | 1163HWa0812467422 | NEW | no | no | 0 | 0 | no | 0 | no | Codetext | AllplanAttributes - Positionsnummer_Text: U100
 | H2 Ebene +1 | WI-IW | 1163Wa 0812468008 | yes | Codetext | m² | Trockenbauarbeiten | Wand | Installationswand | WI-IW | 0 | A | 3.75 | 1163HWa0812467422 | NEW | no | no | 0 | 0 | no | 0 | no | Codetext | AllplanAttributes - W_Deckenanschluss: Gleitender Deckenanschluss Fall 03; ash_W_Trockenbau_Qualitäten: 2; Positionsnummer_Text: U100
 | H2 Ebene +1 | Installationsraum | 1163Wa 0812468009 | yes | Codetext | m² | Trockenbauarbeiten | Wand | Installationswand | Installationsraum | 0 | A | 3.75 | 1163HWa0812467422 | NEW | no | no | 0 | 0 | no | 0 | no | Codetext | AllplanAttributes - Positionsnummer_Text: U100
 | H2 Ebene +1 | WI-IW | 1163Wa 0812468007 | yes | Codetext | m² | Trockenbauarbeiten | Wand | Installationswand | WI-IW | 0 | A | 3.75 | 1163HWa0812467424 | NEW | no | no | 0 | 0 | no | 47 | no | Codetext | AllplanAttributes - W_Deckenanschluss: Gleitender Deckenanschluss Fall 03; ash_W_Trockenbau_Qualitäten: 11; Positionsnummer_Text: U100
 | H2 Ebene +1 | Installationsraum | 1163Wa 0812468003 | yes | Codetext | m² | Trockenbauarbeiten | Wand | Installationswand | Installationsraum | 0 | A | 3.75 | 1163HWa0812467424 | NEW | no | no | 0 | 0 | no | 0 | no | Codetext | AllplanAttributes - Positionsnummer_Text: U100
 | H2 Ebene +1 | WI-IW | 1163Wa 0812468004 | yes | Codetext | m² | Trockenbauarbeiten | Wand | Installationswand | WI-IW | 0 | A | 3.75 | 1163HWa0812467424 | NEW | no | no | 0 | 0 | no | 47 | no | Codetext | AllplanAttributes - W_Deckenanschluss: Gleitender Deckenanschluss Fall 03; ash_W_Trockenbau_Qualitäten: 11; Positionsnummer_Text: U100
 | H2 Ebene +1 | WI-IW | 1163Wa 0812468005 | yes | Codetext | m² | Trockenbauarbeiten | Wand | Installationswand | WI-IW | 0 | A | 3.75 | 1163HWa0812467422 | NEW | no | no | 0 | 0 | no | 0 | no | Codetext | AllplanAttributes - W_Deckenanschluss: Gleitender Deckenanschluss Fall 03; ash_W_Trockenbau_Qualitäten: 2; Positionsnummer_Text: U100
 | H2 Ebene +1 | Installationsraum | 1163Wa 0812468006 | yes | Codetext | m² | Trockenbauarbeiten | Wand | Installationswand | Installationsraum | 0 | A | 3.75 | 1163HWa0812467422 | NEW | no | no | 0 | 0 | no | 0 | no | Codetext | AllplanAttributes - Positionsnummer_Text: U100
 | H2 Ebene +1 | WI-IW | 1163Wa 0812468047 | yes | Codetext | m² | Trockenbauarbeiten | Wand | Installationswand | WI-IW | 0 | A | 3.75 | 1163HWa0812467422 | NEW | no | no | 0 | 0 | no | 0 | no | Codetext | AllplanAttributes - W_Deckenanschluss: Gleitender Deckenanschluss Fall 03; ash_W_Trockenbau_Qualitäten: 2; Positionsnummer_Text: U100
 | H2 Ebene +1 | Installationsraum | 1163Wa 0812468046 | yes | Codetext | m² | Trockenbauarbeiten | Wand | Installationswand | Installationsraum | 0 | A | 3.75 | 1163HWa0812467422 | NEW | no | no | 0 | 0 | no | 0 | no | Codetext | AllplanAttributes - Positionsnummer_Text: U100
 | H2 Ebene +1 | WI-IW | 1163Wa 0812468045 | yes | Codetext | m² | Trockenbauarbeiten | Wand | Installationswand | WI-IW | 0 | A | 3.75 | 1163HWa0812467424 | NEW | no | no | 0 | 0 | no | 47 | no | Codetext | AllplanAttributes - W_Deckenanschluss: Gleitender Deckenanschluss Fall 03; ash_W_Trockenbau_Qualitäten: 11; Positionsnummer_Text: U100
 | H2 Ebene +1 | Installationsraum | 1163Wa 0812468049 | yes | Codetext | m² | Trockenbauarbeiten | Wand | Installationswand | Installationsraum | 0 | A | 3.75 | 1163HWa0812467424 | NEW | no | no | 0 | 0 | no | 0 | no | Codetext | AllplanAttributes - Positionsnummer_Text: U100
 | H2 Ebene +1 | WI-IW | 1163Wa 0812468048 | yes | Codetext | m² | Trockenbauarbeiten | Wand | Installationswand | WI-IW | 0 | A | 3.75 | 1163HWa0812467424 | NEW | no | no | 0 | 0 | no | 47 | no | Codetext | AllplanAttributes - W_Deckenanschluss: Gleitender Deckenanschluss Fall 03; ash_W_Trockenbau_Qualitäten: 11; Positionsnummer_Text: U100
 | H2 Ebene +1 | WI-IW | 1163Wa 0812468044 | yes | Codetext | m² | Trockenbauarbeiten | Wand | Installationswand | WI-IW | 0 | A | 3.75 | 1163HWa0812467422 | NEW | no | no | 0 | 0 | no | 0 | no | Codetext | AllplanAttributes - W_Deckenanschluss: Gleitender Deckenanschluss Fall 03; ash_W_Trockenbau_Qualitäten: 2; Positionsnummer_Text: U100
 | H2 Ebene +1 | Installationsraum | 1163Wa 0812468043 | yes | Codetext | m² | Trockenbauarbeiten | Wand | Installationswand | Installationsraum | 0 | A | 3.75 | 1163HWa0812467422 | NEW | no | no | 0 | 0 | no | 0 | no | Codetext | AllplanAttributes - Positionsnummer_Text: U100
 | H2 Ebene +1 | WI-IW | 1163Wa 0812468146 | yes | Codetext | m² | Trockenbauarbeiten | Wand | Installationswand | WI-IW | 0 | A | 3.75 | 1163HWa0812467422 | NEW | no | no | 0 | 0 | no | 0 | no | Codetext | AllplanAttributes - W_Deckenanschluss: Gleitender Deckenanschluss Fall 03; ash_W_Trockenbau_Qualitäten: 2; Positionsnummer_Text: U100
 | H2 Ebene +1 | Installationsraum | 1163Wa 0812468147 | yes | Codetext | m² | Trockenbauarbeiten | Wand | Installationswand | Installationsraum | 0 | A | 3.75 | 1163HWa0812467422 | NEW | no | no | 0 | 0 | no | 0 | no | Codetext | AllplanAttributes - Positionsnummer_Text: U100
 | H2 Ebene +1 | WI-IW | 1163Wa 0812468148 | yes | Codetext | m² | Trockenbauarbeiten | Wand | Installationswand | WI-IW | 0 | A | 3.75 | 1163HWa0812467424 | NEW | no | no | 0 | 0 | no | 47 | no | Codetext | AllplanAttributes - W_Deckenanschluss: Gleitender Deckenanschluss Fall 03; ash_W_Trockenbau_Qualitäten: 11; Positionsnummer_Text: U100
 | H2 Ebene +1 | Installationsraum | 1163Wa 0812468144 | yes | Codetext | m² | Trockenbauarbeiten | Wand | Installationswand | Installationsraum | 0 | A | 3.75 | 1163HWa0812467424 | NEW | no | no | 0 | 0 | no | 0 | no | Codetext | AllplanAttributes - Positionsnummer_Text: U100
 | H2 Ebene +1 | WI-IW | 1163Wa 0812468145 | yes | Codetext | m² | Trockenbauarbeiten | Wand | Installationswand | WI-IW | 0 | A | 3.75 | 1163HWa0812467424 | NEW | no | no | 0 | 0 | no | 47 | no | Codetext | AllplanAttributes - W_Deckenanschluss: Gleitender Deckenanschluss Fall 03; ash_W_Trockenbau_Qualitäten: 11; Positionsnummer_Text: U100
 | H2 Ebene +1 | WI-IW | 1163Wa 0812468149 | yes | Codetext | m² | Trockenbauarbeiten | Wand | Installationswand | WI-IW | 0 | A | 3.75 | 1163HWa0812467422 | NEW | no | no | 0 | 0 | no | 0 | no | Codetext | AllplanAttributes - W_Deckenanschluss: Gleitender Deckenanschluss Fall 03; ash_W_Trockenbau_Qualitäten: 2; Positionsnummer_Text: U100
 | H2 Ebene +1 | Installationsraum | 1163Wa 0812468150 | yes | Codetext | m² | Trockenbauarbeiten | Wand | Installationswand | Installationsraum | 0 | A | 3.75 | 1163HWa0812467422 | NEW | no | no | 0 | 0 | no | 0 | no | Codetext | AllplanAttributes - Positionsnummer_Text: U100
 | H2 Ebene +1 | WI-IW | 1163Wa 0812468108 | yes | Codetext | m² | Trockenbauarbeiten | Wand | Installationswand | WI-IW | 0 | A | 3.75 | 1163HWa0812467422 | NEW | no | no | 0 | 0 | no | 0 | no | Codetext | AllplanAttributes - W_Deckenanschluss: Gleitender Deckenanschluss Fall 03; ash_W_Trockenbau_Qualitäten: 2; Positionsnummer_Text: U100
 | H2 Ebene +1 | Installationsraum | 1163Wa 0812468107 | yes | Codetext | m² | Trockenbauarbeiten | Wand | Installationswand | Installationsraum | 0 | A | 3.75 | 1163HWa0812467422 | NEW | no | no | 0 | 0 | no | 0 | no | Codetext | AllplanAttributes - Positionsnummer_Text: U100
 | H2 Ebene +1 | WI-IW | 1163Wa 0812468106 | yes | Codetext | m² | Trockenbauarbeiten | Wand | Installationswand | WI-IW | 0 | A | 3.75 | 1163HWa0812467424 | NEW | no | no | 0 | 0 | no | 47 | no | Codetext | AllplanAttributes - W_Deckenanschluss: Gleitender Deckenanschluss Fall 03; ash_W_Trockenbau_Qualitäten: 11; Positionsnummer_Text: U100
 | H2 Ebene +1 | Installationsraum | 1163Wa 0812468110 | yes | Codetext | m² | Trockenbauarbeiten | Wand | Installationswand | Installationsraum | 0 | A | 3.75 | 1163HWa0812467424 | NEW | no | no | 0 | 0 | no | 0 | no | Codetext | AllplanAttributes - Positionsnummer_Text: U100
 | H2 Ebene +1 | WI-IW | 1163Wa 0812468109 | yes | Codetext | m² | Trockenbauarbeiten | Wand | Installationswand | WI-IW | 0 | A | 3.75 | 1163HWa0812467424 | NEW | no | no | 0 | 0 | no | 47 | no | Codetext | AllplanAttributes - W_Deckenanschluss: Gleitender Deckenanschluss Fall 03; ash_W_Trockenbau_Qualitäten: 11; Positionsnummer_Text: U100
 | H2 Ebene +1 | WI-IW | 1163Wa 0812468105 | yes | Codetext | m² | Trockenbauarbeiten | Wand | Installationswand | WI-IW | 0 | A | 3.75 | 1163HWa0812467422 | NEW | no | no | 0 | 0 | no | 0 | no | Codetext | AllplanAttributes - W_Deckenanschluss: Gleitender Deckenanschluss Fall 03; ash_W_Trockenbau_Qualitäten: 2; Positionsnummer_Text: U100
 | H2 Ebene +1 | Installationsraum | 1163Wa 0812468104 | yes | Codetext | m² | Trockenbauarbeiten | Wand | Installationswand | Installationsraum | 0 | A | 3.75 | 1163HWa0812467422 | NEW | no | no | 0 | 0 | no | 0 | no | Codetext | AllplanAttributes - Positionsnummer_Text: U100
 | H2 Ebene +1 | WI-IW | 1163Wa 0812468748 | yes | Codetext | m² | Trockenbauarbeiten | Wand | Installationswand | WI-IW | 0 | A | 3.75 | 1163HWa0812467422 | NEW | no | no | 0 | 0 | no | 0 | no | Codetext | AllplanAttributes - W_Deckenanschluss: Gleitender Deckenanschluss Fall 03; ash_W_Trockenbau_Qualitäten: 2; Positionsnummer_Text: U100
 | H2 Ebene +1 | Installationsraum | 1163Wa 0812468749 | yes | Codetext | m² | Trockenbauarbeiten | Wand | Installationswand | Installationsraum | 0 | A | 3.75 | 1163HWa0812467422 | NEW | no | no | 0 | 0 | no | 0 | no | Codetext | AllplanAttributes - Positionsnummer_Text: U100
 | H2 Ebene +1 | WI-IW | 1163Wa 0812468751 | yes | Codetext | m² | Trockenbauarbeiten | Wand | Installationswand | WI-IW | 0 | A | 3.75 | 1163HWa0812467422 | NEW | no | no | 0 | 0 | no | 0 | no | Codetext | AllplanAttributes - W_Deckenanschluss: Gleitender Deckenanschluss Fall 03; ash_W_Trockenbau_Qualitäten: 2; Positionsnummer_Text: U100
 | H2 Ebene +1 | Installationsraum | 1163Wa 0812468750 | yes | Codetext | m² | Trockenbauarbeiten | Wand | Installationswand | Installationsraum | 0 | A | 3.75 | 1163HWa0812467422 | NEW | no | no | 0 | 0 | no | 0 | no | Codetext | AllplanAttributes - Positionsnummer_Text: U100
 | H2 Ebene +1 | WI-LB | 1163Wa 0812542415 | yes | Codetext | m² | Trockenbauarbeiten | Wand | Innenwand 1-Schalig | WI-LB | 0 | A | 3.75 | 1163HWa0812542405 | NEW | no | no | REI 60-A1 - D,s2-d0 /A1 | 0 | no | 0 | no | Codetext | AllplanAttributes - Ortscode_Geschoßbezeichnung: E01; ash_W_Trockenbau_Qualitäten: 13; Positionsnummer_Text: U100
 | H2 Ebene +1 | WI-LB | 1163Wa 0812543591 | yes | Codetext | m² | Trockenbauarbeiten | Wand | Innenwand 1-Schalig | WI-LB | 0 | A | 3.75 | 1163HWa0812543589 | NEW |  | no | REI 60-A1 - D,s2-d0 /A1 | 0 | no | 0 | no | Codetext | AllplanAttributes - Ortscode_Geschoßbezeichnung: E01; ash_W_Trockenbau_Qualitäten: 13; Positionsnummer_Text: U100
 | H2 Ebene +1 | WI-LW 60 | 1163Wa 0812440294 | yes |  | m² | Trockenbauarbeiten | Wand | Innenwand 1-Schalig | WI-LW 60 |  |  | 3.75 | 1163HWa0812434291 | NEW | yes | no | 0 | AllplanAttributes - ash_W_Trockenbau_Qualitäten: 12a; Positionsnummer_Text: U100
 | H2 Ebene +1 | WI-LW 60 | 1163Wa 0812446937 | yes |  | m² | Trockenbauarbeiten | Wand | Innenwand 1-Schalig | WI-LW 60 |  |  | 3.75 | 1163HWa0812434291 | NEW | yes | no | 0 | AllplanAttributes - ash_W_Trockenbau_Qualitäten: 12a; Positionsnummer_Text: U100
 | H2 Ebene +1 | WI-LB | 1163Wa 0812440015 | yes | Codetext | m² | Trockenbauarbeiten | Wand | Innenwand 1-Schalig | WI-LB | 0 | A | 3.75 | 1113HWa0812959982 | NEW | no | no | REI 60-A1 - D,s2-d0 /A1 | 0 | no | 0 | no | Codetext | AllplanAttributes - ash_W_Trockenbau_Qualitäten: 6; Sicherheitsklasse: -; Positionsnummer_Text: U100
 | H2 Ebene +1 | WI-HW 60 | 1163Wa 0814124424 | yes |  | m² | Zimmer- und Holzbauarbeiten | Wand | Innenwand 1-Schalig | WI-HW 60 |  |  | 3.75 | 1163HWa0812437912 | NEW | yes | no | REI-M 60-D,s2,d0 + A1 |  |  | 47 | AllplanAttributes - ash W_laufende Nr. Statik: 7 (W 6.0-1); Positionsnummer_Text: U100
 | H2 Ebene +1 | WI-LB | 1163Wa 0812542269 | yes | Codetext | m² | Trockenbauarbeiten | Wand | Innenwand 1-Schalig | WI-LB | 0 | A | 3.75 | 1163HWa0812542251 | NEW | no | no | REI 60-A1 - D,s2-d0 /A1 | 0 | no | 0 | no | Codetext | AllplanAttributes - Ortscode_Geschoßbezeichnung: E01; ash_W_Trockenbau_Qualitäten: 13; Positionsnummer_Text: U100
 | H2 Ebene +1 | WI-LB | 1163Wa 0812542173 | yes | Codetext | m² | Trockenbauarbeiten | Wand | Innenwand 1-Schalig | WI-LB | 0 | A | 3.75 | 1163HWa0812542152 | NEW | no | no | REI 60-A1 - D,s2-d0 /A1 | 0 | no | 0 | no | Codetext | AllplanAttributes - Ortscode_Geschoßbezeichnung: E01; ash_W_Trockenbau_Qualitäten: 13; Positionsnummer_Text: U100
 | H2 Ebene +1 | WI-LB | 1163Wa 0813801277 | yes | Codetext | m² | Trockenbauarbeiten | Wand | Innenwand 1-Schalig | WI-LB | 0 | A | 3.75 | 1163HWa0813801276 | NEW | no | no | 0 | 0 | no | 0 | no | Codetext | AllplanAttributes - ash_W_Trockenbau_Qualitäten: 18; Positionsnummer_Text: U100
 | H2 Ebene +1 | WI-LB | 1163Wa 0813711711 | yes | Codetext | m² | Trockenbauarbeiten | Wand | Innenwand 1-Schalig | WI-LB | 0 | A | 3.75 | 1163HWa0813711708 | NEW | no | no | 0 | 0 | no | 0 | no | Codetext | AllplanAttributes - ash_W_Trockenbau_Qualitäten: 8; Positionsnummer_Text: U100
 | H2 Ebene +1 | WI-LB | 1163Wa 0813711674 | yes | Codetext | m² | Trockenbauarbeiten | Wand | Innenwand 1-Schalig | WI-LB | 0 | A | 3.75 | 1163HWa0813711672 | NEW | no | no | 0 | 0 | no | 0 | no | Codetext | AllplanAttributes - ash_W_Trockenbau_Qualitäten: 8; Positionsnummer_Text: U100
 | H2 Ebene +1 | WI-LB | 1163Wa 0813711848 | yes | Codetext | m² | Trockenbauarbeiten | Wand | Innenwand 1-Schalig | WI-LB | 0 | A | 3.75 | 1163HWa0813711832 | NEW | no | no | 0 | 0 | no | 0 | no | Codetext | AllplanAttributes - ash_W_Trockenbau_Qualitäten: 16; Positionsnummer_Text: U100
 | H2 Ebene +1 | Installationsraum | 1163Wa 0812442539 | yes | Codetext | m² | Trockenbauarbeiten | Wand | Installationswand | Installationsraum | 0 | A | 3.75 | 1163HWa0812425591 | NEW | no | no | 0 | 0 | no | 0 | no | Codetext | AllplanAttributes - Positionsnummer_Text: U100
 | H2 Ebene +1 | WI-VS | 1163Wa 0812442545 | yes | Codetext | m² | Trockenbauarbeiten | Wand | Installationswand | WI-VS | 0 | A | 3.75 | 1163HWa0812425591 | NEW | no | no | 0 | 0 | no | 0 | no | Codetext | AllplanAttributes - W_Deckenanschluss: Gleitender Deckenanschluss Fall 01; ash_W_Trockenbau_Qualitäten: 18; Positionsnummer_Text: U100
 | H2 Ebene +1 | WI-IW | 1163Wa 0813718679 | yes | Codetext | m² | Trockenbauarbeiten | Wand | Installationswand | WI-IW | 0 | A | 3.75 | 1163HWa0813718678 | NEW | no | no | 0 | 0 | no | 0 | no | Codetext | AllplanAttributes - ash_W_Trockenbau_Qualitäten: 16; Positionsnummer_Text: U100
 | H2 Ebene +1 | WI-LB | 1163Wa 0812551363 | yes | Codetext | m² | Trockenbauarbeiten | Wand | Innenwand 1-Schalig | WI-LB | 0 | A | 3.75 | 1163HWa0812551348 | NEW | no | no | REI 30-A1 - D,s2-d0 +A1 | 0 | no | 0 | no | Codetext | AllplanAttributes - ash_W_Trockenbau_Qualitäten: 16; Positionsnummer_Text: U100
 | H2 Ebene +1 | WI-HW 60 | 1163Wa 0814104879 | yes | Codetext | m² | Zimmer- und Holzbauarbeiten | Wand | Innenwand 1-Schalig | WI-HW 60 | 0 | A | 3.75 | 1163HWa0812551348 | NEW | no | no | REI 30-A1 - D,s2-d0 +A1 | 0 | no | 0 | no | Codetext | AllplanAttributes - ash W_laufende Nr. Statik: 1 (W 1.0/ 1.1/ 1.2); Positionsnummer_Text: U100
 | H2 Ebene +1 | WI-LB | 1163Wa 0813801209 | yes | Codetext | m² | Trockenbauarbeiten | Wand | Innenwand 1-Schalig | WI-LB | 0 | A | 3.75 | 1163HWa0813801208 | NEW | no | no | 0 | 0 | no | 0 | no | Codetext | AllplanAttributes - ash_W_Trockenbau_Qualitäten: 18; Positionsnummer_Text: U100
 | H2 Ebene +1 | WI-VS | 1163Wa 0813718604 | yes | Codetext | m² | Trockenbauarbeiten | Wand | Installationswand | WI-VS | 0 | A | 3.75 | 1163HWa0813718603 | NEW | no | no | 0 | 0 | no | 0 | no | Codetext | AllplanAttributes - ash_W_Trockenbau_Qualitäten: 16; Positionsnummer_Text: U100
 | H2 Ebene +1 | WI-LB | 1163Wa 0812443005 | yes | Codetext | m² | Trockenbauarbeiten | Wand | Innenwand 1-Schalig | WI-LB | 0 | A | 3.75 | 1163HWa0812441885 | NEW | no | no | REI 30-A1 - D,s2-d0 +A1 | 0 | no | 0 | no | Codetext | AllplanAttributes - ash_W_Trockenbau_Qualitäten: 16; Positionsnummer_Text: U100
 | H2 Ebene +1 | WI-HW 60 | 1163Wa 0813777055 | yes | Codetext | m² | Zimmer- und Holzbauarbeiten | Wand | Innenwand 1-Schalig | WI-HW 60 | 0 | A | 3.75 | 1163HWa0812441885 | NEW | no | no | REI 30-A1 - D,s2-d0 +A1 | 0 | no | 0 | no | Codetext | AllplanAttributes - ash W_laufende Nr. Statik: 3 (W 3.0); Positionsnummer_Text: U100
 | H2 Ebene +1 | WI-VS | 1163Wa 0812443017 | yes | Codetext | m² | Trockenbauarbeiten | Wand | Innenwand 1-Schalig | WI-VS | 0 | A | 3.75 | 1163HWa0812463423 | NEW | no | no | 0 | 0 | no | 0 | no | Codetext | AllplanAttributes - W_Deckenanschluss: Gleitender Deckenanschluss Fall 01; ash_W_Trockenbau_Qualitäten: 11; Positionsnummer_Text: U100
 | H2 Ebene +1 | Installationsraum | 1163Wa 0814713014 | yes | Codetext | m² | Trockenbauarbeiten | Wand | Innenwand 1-Schalig | Installationsraum | 0 | A | 3.75 | 1163HWa0812463423 | NEW | no | no | 0 | 0 | no | 0 | no | Codetext | AllplanAttributes - Positionsnummer_Text: U100
 | H2 Ebene +1 | WI-LB | 1163Wa 0814713015 | yes | Codetext | m² | Trockenbauarbeiten | Wand | Innenwand 1-Schalig | WI-LB | 0 | A | 3.75 | 1163HWa0812441876 | NEW | no | no | REI 30-A1 - D,s2-d0 +A1 | 0 | no | 0 | no | Codetext | AllplanAttributes - W_Deckenanschluss: Gleitender Deckenanschluss Fall 01; ash_W_Trockenbau_Qualitäten: 11; Positionsnummer_Text: U100
 | H2 Ebene +1 | WI-LB | 1163Wa 0814537156 | yes | Codetext | m² | Trockenbauarbeiten | Wand | Innenwand 1-Schalig | WI-LB | 0 | A | 3.75 | 1163HWa0812441885 | NEW | no | no | REI 30-A1 - D,s2-d0 +A1 | 0 | no | 0 | no | Codetext | AllplanAttributes - ash_W_Trockenbau_Qualitäten: 16; Positionsnummer_Text: U100
 | H2 Ebene +1 | WI-HW 60 | 1163Wa 0814537158 | yes | Codetext | m² | Zimmer- und Holzbauarbeiten | Wand | Innenwand 1-Schalig | WI-HW 60 | 0 | A | 3.75 | 1163HWa0812441885 | NEW | no | no | REI 30-A1 - D,s2-d0 +A1 | 0 | no | 0 | no | Codetext | AllplanAttributes - ash W_laufende Nr. Statik: 3 (W 3.0); Positionsnummer_Text: U100
 | H2 Ebene +1 | Installationsraum | 1163Wa 0812463424 | yes | Codetext | m² | Trockenbauarbeiten | Wand | Installationswand | Installationsraum | 0 | A | 3.75 | 1163HWa0812463423 | NEW | no | no | 0 | 0 | no | 0 | no | Codetext | AllplanAttributes - Positionsnummer_Text: U100
 | H2 Ebene +1 | WI-VS | 1163Wa 0812463425 | yes | Codetext | m² | Trockenbauarbeiten | Wand | Installationswand | WI-VS | 0 | A | 3.75 | 1163HWa0812463423 | NEW | no | no | 0 | 0 | no | 0 | no | Codetext | AllplanAttributes - W_Deckenanschluss: Gleitender Deckenanschluss Fall 01; ash_W_Trockenbau_Qualitäten: 2; Positionsnummer_Text: U100
 | H2 Ebene +1 | Installationsraum | 1163Wa 0814537430 | yes | Codetext | m² | Trockenbauarbeiten | Wand | Installationswand | Installationsraum | 0 | A | 3.75 | 1163HWa0812425821 | NEW | no | no | 0 | 0 | no | 0 | no | Codetext | AllplanAttributes - Ortscode_Geschoßbezeichnung: E01; Positionsnummer_Text: U100
 | H2 Ebene +1 | WI-VS | 1163Wa 0814537429 | yes | Codetext | m² | Trockenbauarbeiten | Wand | Installationswand | WI-VS | 0 | A | 3.75 | 1163HWa0812425821 | NEW | no | no | 0 | 0 | no | 0 | no | Codetext | AllplanAttributes - Ortscode_Geschoßbezeichnung: E01; W_Deckenanschluss: Gleitender Deckenanschluss Fall 01; ash_W_Trockenbau_Qualitäten: 2; Positionsnummer_Text: U100
 | H2 Ebene +1 | WI-VS | 1163Wa 0814509171 | yes | Codetext | m² | Trockenbauarbeiten | Wand | Installationswand | WI-VS | 0 | A | 3.75 | 1163HWa0812425821 | NEW | no | no | 0 | 0 | no | 0 | no | Codetext | AllplanAttributes - W_Deckenanschluss: Gleitender Deckenanschluss Fall 01; ash_W_Trockenbau_Qualitäten: 11; Positionsnummer_Text: U100
 | H2 Ebene +1 | Installationsraum | 1163Wa 0814509172 | yes | Codetext | m² | Trockenbauarbeiten | Wand | Installationswand | Installationsraum | 0 | A | 3.75 | 1163HWa0812425821 | NEW | no | no | 0 | 0 | no | 0 | no | Codetext | AllplanAttributes - Positionsnummer_Text: U100
 | H2 Ebene +1 | WI-VS | 1163Wa 0814509181 | yes | Codetext | m² | Trockenbauarbeiten | Wand | Installationswand | WI-VS | 0 | A | 3.75 | 1163HWa0812425821 | NEW | no | no | 0 | 0 | no | 0 | no | Codetext | AllplanAttributes - W_Deckenanschluss: Gleitender Deckenanschluss Fall 01; ash_W_Trockenbau_Qualitäten: 11; Positionsnummer_Text: U100
 | H2 Ebene +1 | Installationsraum | 1163Wa 0814509517 | yes | Codetext | m² | Trockenbauarbeiten | Wand | Installationswand | Installationsraum | 0 | A | 3.75 | 1163HWa0812425821 | NEW | no | no | 0 | 0 | no | 0 | no | Codetext | AllplanAttributes - Ortscode_Geschoßbezeichnung: E01; Positionsnummer_Text: U100
 | H2 Ebene +1 | WI-VS | 1163Wa 0814509518 | yes | Codetext | m² | Trockenbauarbeiten | Wand | Installationswand | WI-VS | 0 | A | 3.75 | 1163HWa0812425821 | NEW | no | no | 0 | 0 | no | 0 | no | Codetext | AllplanAttributes - Ortscode_Geschoßbezeichnung: E01; W_Deckenanschluss: Gleitender Deckenanschluss Fall 01; ash_W_Trockenbau_Qualitäten: 2; Positionsnummer_Text: U100
 | H2 Ebene +1 | WI-IW | 1163Wa 0812443205 | yes | Codetext | m² | Trockenbauarbeiten | Wand | Installationswand | WI-IW | 0 | A | 3.75 | 1163HWa0812435319 | NEW |  | no | 0 | 0 | no | 47 | no | Codetext | AllplanAttributes - W_Deckenanschluss: Gleitender Deckenanschluss Fall 01; ash_W_Trockenbau_Qualitäten: 19; Positionsnummer_Text: U100
 | H2 Ebene +1 | Installationsraum | 1163Wa 0812443207 | yes | Codetext | m² | Trockenbauarbeiten | Wand | Installationswand | Installationsraum | 0 | A | 3.75 | 1163HWa0812435319 | NEW |  | no | 0 | 0 | no | 0 | no | Codetext | AllplanAttributes - Positionsnummer_Text: U100
 | H2 Ebene +1 | WI-IW | 1163Wa 0814550817 | yes | Codetext | m² | Trockenbauarbeiten | Wand | Installationswand | WI-IW | 0 | A | 3.75 | 1163HWa0812435319 | NEW |  | no | 0 | 0 | no | 47 | no | Codetext | AllplanAttributes - W_Deckenanschluss: Gleitender Deckenanschluss Fall 01; ash_W_Trockenbau_Qualitäten: 19; Positionsnummer_Text: U100
 | H2 Ebene +1 | WI-LB | 1163Wa 0813711734 | yes | Codetext | m² | Trockenbauarbeiten | Wand | Innenwand 1-Schalig | WI-LB | 0 | A | 3.75 | 1163HWa0813711732 | NEW | no | no | 0 | 0 | no | 0 | no | Codetext | AllplanAttributes - ash_W_Trockenbau_Qualitäten: 8; Positionsnummer_Text: U100
 | H2 Ebene +1 | Installationsraum | 1163Wa 0812446745 | yes | Codetext | m² | Trockenbauarbeiten | Wand | Installationswand | Installationsraum | 0 | A | 3.75 | 1163HWa0812434255 | NEW | no | no | 0 | 0 | no | 0 | no | Codetext | AllplanAttributes - Positionsnummer_Text: U100
 | H2 Ebene +1 | WI-VS | 1163Wa 0812446763 | yes | Codetext | m² | Trockenbauarbeiten | Wand | Installationswand | WI-VS | 0 | A | 3.75 | 1163HWa0812434255 | NEW | no | no | 0 | 0 | no | 0 | no | Codetext | AllplanAttributes - W_Deckenanschluss: Gleitender Deckenanschluss Fall 03; ash_W_Trockenbau_Qualitäten: 2; Positionsnummer_Text: U100
 | H2 Ebene +1 | WI-LB | 1163Wa 0813711809 | yes | Codetext | m² | Trockenbauarbeiten | Wand | Innenwand 1-Schalig | WI-LB | 0 | A | 3.75 | 1163HWa0813711807 | NEW | no | no | 0 | 0 | no | 0 | no | Codetext | AllplanAttributes - ash_W_Trockenbau_Qualitäten: 8; Positionsnummer_Text: U100
 | H2 Ebene +1 | Installationsraum | 1163Wa 0812437330 | yes | Codetext | m² | Trockenbauarbeiten | Wand | Installationswand | Installationsraum | 0 | A | 3.75 | 1163HWa0812432276 | NEW | no | no | 0 | 0 | no | 0 | no | Codetext | AllplanAttributes - Positionsnummer_Text: U100
 | H2 Ebene +1 | WI-VS | 1163Wa 0812437328 | yes | Codetext | m² | Trockenbauarbeiten | Wand | Installationswand | WI-VS | 0 | A | 3.75 | 1163HWa0812432276 | NEW | no | no | 0 | 0 | no | 0 | no | Codetext | AllplanAttributes - W_Deckenanschluss: Gleitender Deckenanschluss Fall 01; ash_W_Trockenbau_Qualitäten: 5; Positionsnummer_Text: U100
 | H2 Ebene +1 | Installationsraum | 1163Wa 0812777444 | yes | Codetext | m² | Trockenbauarbeiten | Wand | Installationswand | Installationsraum | 0 | A | 3.75 | 1163HWa0812777443 | NEW | no | no | 0 | 0 | no | 0 | no | Codetext | AllplanAttributes - Positionsnummer_Text: U100
 | H2 Ebene +1 | WI-VS | 1163Wa 0812777445 | yes | Codetext | m² | Trockenbauarbeiten | Wand | Installationswand | WI-VS | 0 | A | 3.75 | 1163HWa0812777443 | NEW | no | no | 0 | 0 | no | 0 | no | Codetext | AllplanAttributes - W_Deckenanschluss: Gleitender Deckenanschluss Fall 01; ash_W_Trockenbau_Qualitäten: 5; Positionsnummer_Text: U100
 | H2 Ebene +1 | WI-IW | 1163Wa 0812464590 | yes | Codetext | m² | Trockenbauarbeiten | Wand | Installationswand | WI-IW | 0 | A | 3.75 | 1163HWa0812464589 | NEW |  | no | 0 | 0 | no | 0 | no | Codetext | AllplanAttributes - W_Deckenanschluss: Gleitender Deckenanschluss Fall 01; ash_W_Trockenbau_Qualitäten: 18; Positionsnummer_Text: U100
 | H2 Ebene +1 | Installationsraum | 1163Wa 0812464591 | yes | Codetext | m² | Trockenbauarbeiten | Wand | Installationswand | Installationsraum | 0 | A | 3.75 | 1163HWa0812464589 | NEW |  | no | 0 | 0 | no | 0 | no | Codetext | AllplanAttributes - Positionsnummer_Text: U100
 | H2 Ebene +1 | WI-LB | 1163Wa 0812512018 | yes | Codetext | m² | Trockenbauarbeiten | Wand | Innenwand 1-Schalig | WI-LB | 0 | A | 3.75 | 1163HWa0812512017 | NEW | no | no | 0 | 0 | no | 52 | no | Codetext | AllplanAttributes - ash_W_Trockenbau_Qualitäten: 8; Sicherheitsklasse: -; Positionsnummer_Text: U100
 | H2 Ebene +1 | Installationsraum | 1163Wa 0813784075 | yes | Codetext | m² | Trockenbauarbeiten | Wand | Innenwand 1-Schalig | Installationsraum | 0 | A | 3.75 | 1163HWa0812512017 | NEW | no | no | 0 | 0 | no | 0 | no | Codetext | AllplanAttributes - Sicherheitsklasse: -; Positionsnummer_Text: U100
 | H2 Ebene +1 | WI-HW 60 | 1163Wa 0814103940 | yes | Codetext | m² | Zimmer- und Holzbauarbeiten | Wand | Innenwand 1-Schalig | WI-HW 60 | 0 | A | 3.75 | 1163HWa0812512017 | NEW | no | no | 0 | 0 | no | 52 | no | Codetext | AllplanAttributes - Sicherheitsklasse: -; ash W_laufende Nr. Statik: 3 (W 3.0); Positionsnummer_Text: U100
 | H2 Ebene +1 | Installationsraum | 1163Wa 0812446835 | yes | Codetext | m² | Trockenbauarbeiten | Wand | Installationswand | Installationsraum | 0 | A | 3.75 | 1163HWa0812435307 | NEW |  | no | 0 | 0 | no | 0 | no | Codetext | AllplanAttributes - Positionsnummer_Text: U100
 | H2 Ebene +1 | WI-VS | 1163Wa 0812446831 | yes | Codetext | m² | Trockenbauarbeiten | Wand | Installationswand | WI-VS | 0 | A | 3.75 | 1163HWa0812435307 | NEW |  | no | 0 | 0 | no | 0 | no | Codetext | AllplanAttributes - W_Deckenanschluss: Gleitender Deckenanschluss Fall 01; ash_W_Trockenbau_Qualitäten: 18; Positionsnummer_Text: U100
 | H2 Ebene +1 | WI-VS | 1163Wa 0813718619 | yes | Codetext | m² | Trockenbauarbeiten | Wand | Installationswand | WI-VS | 0 | A | 3.75 | 1163HWa0813718618 | NEW | no | no | 0 | 0 | no | 47 | no | Codetext | AllplanAttributes - ash_W_Trockenbau_Qualitäten: 8; Positionsnummer_Text: U100
 | H2 Ebene +1 | WI-LB | 1163Wa 0812446944 | yes | Codetext | m² | Trockenbauarbeiten | Wand | Innenwand 1-Schalig | WI-LB | 0 | A | 3.75 | 1163HWa0812446942 | NEW | no | no | REI 60-A1 - D,s2-d0 /A1 | 0 | no | 52 | no | Codetext | AllplanAttributes - ash_W_Trockenbau_Qualitäten: 6; Positionsnummer_Text: U100
 | H2 Ebene +1 | WI-HW 60 | 1163Wa 0814104080 | yes |  | m² | Zimmer- und Holzbauarbeiten | Wand | Innenwand 1-Schalig | WI-HW 60 |  |  | 3.75 | 1163HWa0812446942 | NEW | no | no | REI-M 60-D,s2,d0 + A1 |  |  | 52 | AllplanAttributes - ash W_laufende Nr. Statik: 7 (W 6.0-1); Positionsnummer_Text: U100
 | H2 Ebene +1 | Installationsraum | 1163Wa 0812446948 | yes | Codetext | m² | Trockenbauarbeiten | Wand | Installationswand | Installationsraum | 0 | A | 3.75 | 1163HWa0812430885 | NEW | no | no | 0 | 0 | no | 0 | no | Codetext | AllplanAttributes - Positionsnummer_Text: U100
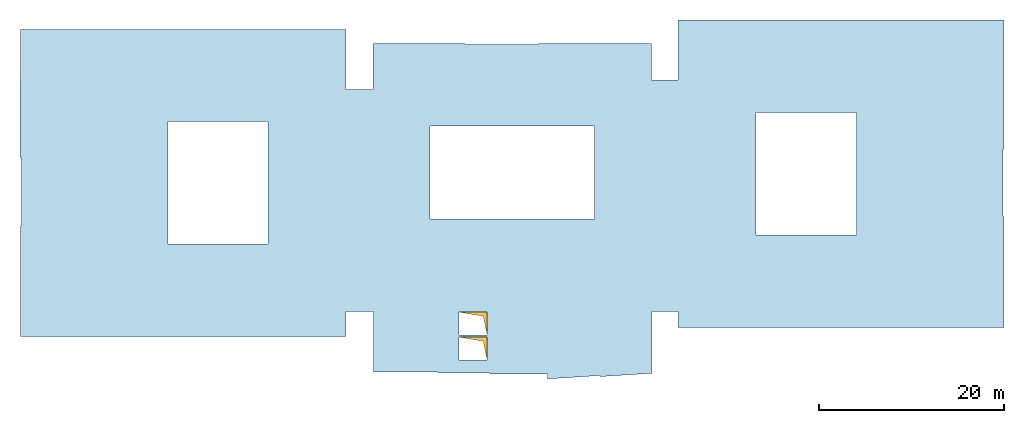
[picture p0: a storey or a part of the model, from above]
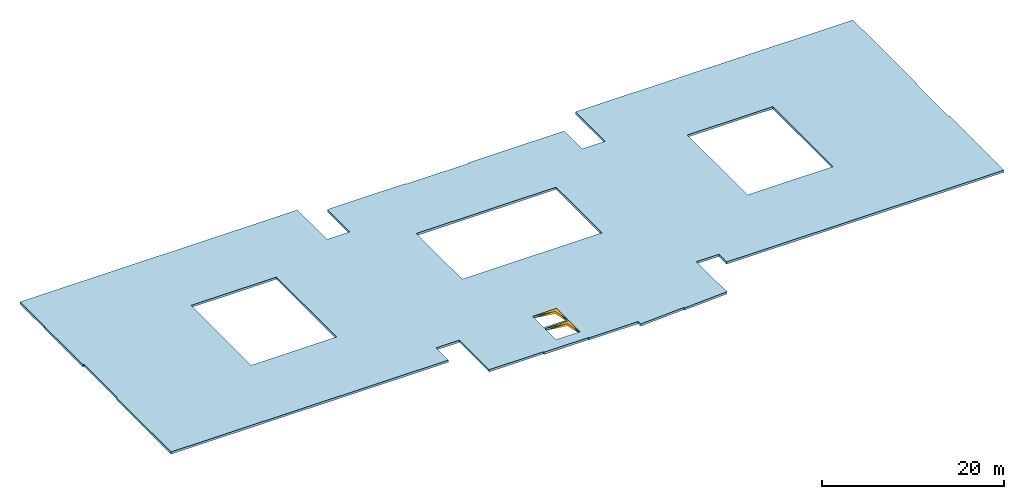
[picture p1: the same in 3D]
Properties of the parts of a building model (IFC4), part 68 of 80

# IfcWall (6826)
Name | In | Material | Allright_Bauteil_ID | 2D Interaktion | Codetext | Abrechnungsart | Gewerk | Objektname | Bezeichnung | AllplanAttributes, Material | Typ = SurfaceSpreadOfFlame | Brandschutzklasse | OKFF | P_ID | Status | LoadBearing | IsExternal | FireRating | ThermalTransmittance (W/K/m2) | Combustible | AcousticRating | Compartmentation | Reference
 | H2 Ebene +1 | WI-VS | 1163Wa 0812446895 | yes | Codetext | m² | Trockenbauarbeiten | Wand | Installationswand | WI-VS | 0 | A | 3.75 | 1163HWa0812430885 | NEW | no | no | 0 | 0 | no | 0 | no | Codetext | AllplanAttributes - W_Deckenanschluss: Gleitender Deckenanschluss Fall 01; ash_W_Trockenbau_Qualitäten: 2; Positionsnummer_Text: U100
 | H2 Ebene +1 | WI-IW | 1163Wa 0812437266 | yes | Codetext | m² | Trockenbauarbeiten | Wand | Installationswand | WI-IW | 0 | A | 3.75 | 1163HWa0812429077 | NEW | no | no | 0 | 0 | no | 0 | no | Codetext | AllplanAttributes - W_Deckenanschluss: Gleitender Deckenanschluss Fall 01; ash_W_Trockenbau_Qualitäten: 11; Positionsnummer_Text: U100
 | H2 Ebene +1 | Installationsraum | 1163Wa 0812437268 | yes | Codetext | m² | Trockenbauarbeiten | Wand | Installationswand | Installationsraum | 0 | A | 3.75 | 1163HWa0812429077 | NEW | no | no | 0 | 0 | no | 0 | no | Codetext | AllplanAttributes - Positionsnummer_Text: U100
 | H2 Ebene +1 | WI-IW | 1163Wa 0812437270 | yes | Codetext | m² | Trockenbauarbeiten | Wand | Installationswand | WI-IW | 0 | A | 3.75 | 1163HWa0812429077 | NEW | no | no | 0 | 0 | no | 0 | no | Codetext | AllplanAttributes - W_Deckenanschluss: Gleitender Deckenanschluss Fall 01; ash_W_Trockenbau_Qualitäten: 11; Positionsnummer_Text: U100
 | H2 Ebene +1 | Installationsraum | 1163Wa 0812439605 | yes | Codetext | m² | Trockenbauarbeiten | Wand | Installationswand | Installationsraum | 0 | A | 3.75 | 1163HWa0812425593 | NEW | no | no | 0 | 0 | no | 0 | no | Codetext | AllplanAttributes - Positionsnummer_Text: U100
 | H2 Ebene +1 | WI-VS | 1163Wa 0812439611 | yes | Codetext | m² | Trockenbauarbeiten | Wand | Installationswand | WI-VS | 0 | A | 3.75 | 1163HWa0812425593 | NEW | no | no | 0 | 0 | no | 0 | no | Codetext | AllplanAttributes - W_Deckenanschluss: Gleitender Deckenanschluss Fall 01; ash_W_Trockenbau_Qualitäten: 18; Positionsnummer_Text: U100
 | H2 Ebene +1 | WI-HW 60 | 1163Wa 0812551371 | yes | Codetext | m² | Zimmer- und Holzbauarbeiten | Wand | Innenwand 1-Schalig | WI-HW 60 | 0 | A | 3.75 | 1163HWa0812551366 | NEW | no | no | REI 30-A1 - D,s2-d0 +A1 | 0 | no | 0 | no | Codetext | AllplanAttributes - ash W_laufende Nr. Statik: 1 (W 1.0/ 1.1/ 1.2); Positionsnummer_Text: U100
 | H2 Ebene +1 | WI-LB | 1163Wa 0814105097 | yes | Codetext | m² | Trockenbauarbeiten | Wand | Innenwand 1-Schalig | WI-LB | 0 | A | 3.75 | 1163HWa0812551366 | NEW | no | no | REI 30-A1 - D,s2-d0 +A1 | 0 | no | 0 | no | Codetext | AllplanAttributes - ash_W_Trockenbau_Qualitäten: 6; Positionsnummer_Text: U100
 | H2 Ebene +1 | WI-IW | 1163Wa 0813714676 | yes | Codetext | m² | Trockenbauarbeiten | Wand | Installationswand | WI-IW | 0 | A | 3.75 | 1163HWa0812435319 | NEW |  | no | 0 | 0 | no | 47 | no | Codetext | AllplanAttributes - W_Deckenanschluss: Gleitender Deckenanschluss Fall 01; ash_W_Trockenbau_Qualitäten: 14; Positionsnummer_Text: U100
 | H2 Ebene +1 | Installationsraum | 1163Wa 0814613300 | yes | Codetext | m² | Trockenbauarbeiten | Wand | Installationswand | Installationsraum | 0 | A | 3.75 | 1163HWa0812435319 | NEW |  | no | 0 | 0 | no | 0 | no | Codetext | AllplanAttributes - Positionsnummer_Text: U100
 | H2 Ebene +1 | WI-IW | 1163Wa 0814613301 | yes | Codetext | m² | Trockenbauarbeiten | Wand | Installationswand | WI-IW | 0 | A | 3.75 | 1163HWa0812435319 | NEW |  | no | 0 | 0 | no | 47 | no | Codetext | AllplanAttributes - W_Deckenanschluss: Gleitender Deckenanschluss Fall 01; ash_W_Trockenbau_Qualitäten: 14; Positionsnummer_Text: U100
 | H2 Ebene +1 | WI-LB | 1163Wa 0813711867 | yes | Codetext | m² | Trockenbauarbeiten | Wand | Innenwand 1-Schalig | WI-LB | 0 | A | 3.75 | 1163HWa0813711851 | NEW | no | no | 0 | 0 | no | 0 | no | Codetext | AllplanAttributes - ash_W_Trockenbau_Qualitäten: 6; Positionsnummer_Text: U100
 | H2 Ebene +1 | WI-IW | 1163Wa 0812464234 | yes | Codetext | m² | Trockenbauarbeiten | Wand | Installationswand | WI-IW | 0 | A | 3.75 | 1163HWa0812464233 | NEW |  | no | 0 | 0 | no | 0 | no | Codetext | AllplanAttributes - W_Deckenanschluss: Gleitender Deckenanschluss Fall 01; ash_W_Trockenbau_Qualitäten: 18; Positionsnummer_Text: U100
 | H2 Ebene +1 | Installationsraum | 1163Wa 0812464235 | yes | Codetext | m² | Trockenbauarbeiten | Wand | Installationswand | Installationsraum | 0 | A | 3.75 | 1163HWa0812464233 | NEW |  | no | 0 | 0 | no | 0 | no | Codetext | AllplanAttributes - Positionsnummer_Text: U100
 | H2 Ebene +1 | WI-IW | 1163Wa 0814706379 | yes | Codetext | m² | Trockenbauarbeiten | Wand | Installationswand | WI-IW | 0 | A | 3.75 | 1163HWa0812464233 | NEW |  | no | 0 | 0 | no | 0 | no | Codetext | AllplanAttributes - W_Deckenanschluss: Gleitender Deckenanschluss Fall 01; ash_W_Trockenbau_Qualitäten: 18; Positionsnummer_Text: U100
 | H2 Ebene +1 | Installationsraum | 1163Wa 0814706380 | yes | Codetext | m² | Trockenbauarbeiten | Wand | Installationswand | Installationsraum | 0 | A | 3.75 | 1163HWa0812464233 | NEW |  | no | 0 | 0 | no | 0 | no | Codetext | AllplanAttributes - Positionsnummer_Text: U100
 | H2 Ebene +1 | WI-IW | 1163Wa 0813718635 | yes | Codetext | m² | Trockenbauarbeiten | Wand | Installationswand | WI-IW | 0 | A | 3.75 | 1163HWa0813718634 | NEW | no | no | 0 | 0 | no | 0 | no | Codetext | AllplanAttributes - ash_W_Trockenbau_Qualitäten: 16; Positionsnummer_Text: U100
 | H2 Ebene +1 | WI-LB | 1163Wa 0812439882 | yes | Codetext | m² | Trockenbauarbeiten | Wand | Innenwand 1-Schalig | WI-LB | 0 | A | 3.75 | 1163HWa0812429054 | NEW | no | no | 0 | 0 | no | 47 | no | Codetext | AllplanAttributes - ash_W_Trockenbau_Qualitäten: 17; Sicherheitsklasse: -; Positionsnummer_Text: U100
 | H2 Ebene +1 | Installationsraum | 1163Wa 0813788738 | yes | Codetext | m² | Trockenbauarbeiten | Wand | Innenwand 1-Schalig | Installationsraum | 0 | A | 3.75 | 1163HWa0812429054 | NEW | no | no | 0 | 0 | no | 0 | no | Codetext | AllplanAttributes - Sicherheitsklasse: -; Positionsnummer_Text: U100
 | H2 Ebene +1 | WI-HW 60 | 1163Wa 0814104476 | yes | Codetext | m² | Zimmer- und Holzbauarbeiten | Wand | Innenwand 1-Schalig | WI-HW 60 | 0 | A | 3.75 | 1163HWa0812429054 | NEW | no | no | 0 | 0 | no | 47 | no | Codetext | AllplanAttributes - Sicherheitsklasse: -; ash W_laufende Nr. Statik: 3 (W 3.0); Positionsnummer_Text: U100
 | H2 Ebene +1 | WI-IW | 1163Wa 0814104477 | yes | Codetext | m² | Trockenbauarbeiten | Wand | Innenwand 1-Schalig | WI-IW | 0 | A | 3.75 | 1163HWa0812429054 | NEW | no | no | 0 | 0 | no | 0 | no | Codetext | AllplanAttributes - ash_W_Trockenbau_Qualitäten: 17; Sicherheitsklasse: -; Positionsnummer_Text: U100
 | H2 Ebene +1 | WI-IW | 1163Wa 0812464511 | yes | Codetext | m² | Trockenbauarbeiten | Wand | Installationswand | WI-IW | 0 | A | 3.75 | 1163HWa0812464506 | NEW |  | no | 0 | 0 | no | 0 | no | Codetext | AllplanAttributes - W_Deckenanschluss: Gleitender Deckenanschluss Fall 01; ash_W_Trockenbau_Qualitäten: 18; Positionsnummer_Text: U100
 | H2 Ebene +1 | Installationsraum | 1163Wa 0812464512 | yes | Codetext | m² | Trockenbauarbeiten | Wand | Installationswand | Installationsraum | 0 | A | 3.75 | 1163HWa0812464506 | NEW |  | no | 0 | 0 | no | 0 | no | Codetext | AllplanAttributes - Positionsnummer_Text: U100
 | H2 Ebene +1 | WI-HW 60 | 1163Wa 0812755727 | yes |  | m² | Zimmer- und Holzbauarbeiten | Wand | Innenwand 1-Schalig | WI-HW 60 |  |  | 3.75 | 1163HWa0812755527 | NEW | yes | no | REI-M 60-D,s2,d0 + A1 |  |  | 47 | AllplanAttributes - ash W_laufende Nr. Statik: 7 (W 6.0-1); Positionsnummer_Text: U100
 | H2 Ebene +1 | WI-LB | 1163Wa 0814124375 | yes | Codetext | m² | Trockenbauarbeiten | Wand | Innenwand 1-Schalig | WI-LB | 0 | A | 3.75 | 1113HWa0812959982 | NEW | no | no | REI 60-A1 - D,s2-d0 /A1 | 0 | no | 0 | no | Codetext | AllplanAttributes - ash_W_Trockenbau_Qualitäten: 6; Sicherheitsklasse: -; Positionsnummer_Text: U100
 | H2 Ebene +1 | Installationsraum | 1163Wa 0812447419 | yes | Codetext | m² | Trockenbauarbeiten | Wand | Installationswand | Installationsraum | 0 | A | 3.75 | 1163HWa0812435127 | NEW | no | no | 0 | 0 | no | 0 | no | Codetext | AllplanAttributes - Positionsnummer_Text: U100
 | H2 Ebene +1 | WI-VS | 1163Wa 0812447423 | yes | Codetext | m² | Trockenbauarbeiten | Wand | Installationswand | WI-VS | 0 | A | 3.75 | 1163HWa0812435127 | NEW | no | no | 0 | 0 | no | 0 | no | Codetext | AllplanAttributes - W_Deckenanschluss: Gleitender Deckenanschluss Fall 01; ash_W_Trockenbau_Qualitäten: 2; Positionsnummer_Text: U100
 | H2 Ebene +1 | Installationsraum | 1163Wa 0812944502 | yes | Codetext | m² | Trockenbauarbeiten | Wand | Installationswand | Installationsraum | 0 | A | 3.75 | 1163HWa0812944501 | NEW | no | no | 0 | 0 | no | 0 | no | Codetext | AllplanAttributes - Positionsnummer_Text: U100
 | H2 Ebene +1 | WI-VS | 1163Wa 0812944503 | yes | Codetext | m² | Trockenbauarbeiten | Wand | Installationswand | WI-VS | 0 | A | 3.75 | 1163HWa0812944501 | NEW | no | no | 0 | 0 | no | 0 | no | Codetext | AllplanAttributes - W_Deckenanschluss: Gleitender Deckenanschluss Fall 01; ash_W_Trockenbau_Qualitäten: 2; Positionsnummer_Text: U100
 | H2 Ebene +1 | WI-LB | 1163Wa 0813711648 | yes | Codetext | m² | Trockenbauarbeiten | Wand | Innenwand 1-Schalig | WI-LB | 0 | A | 3.75 | 1163HWa0813711646 | NEW | no | no | 0 | 0 | no | 0 | no | Codetext | AllplanAttributes - ash_W_Trockenbau_Qualitäten: 8; Positionsnummer_Text: U100
 | H2 Ebene +1 | WI-LB | 1163Wa 0813711627 | yes | Codetext | m² | Trockenbauarbeiten | Wand | Innenwand 1-Schalig | WI-LB | 0 | A | 3.75 | 1163HWa0813711625 | NEW | no | no | 0 | 0 | no | 0 | no | Codetext | AllplanAttributes - ash_W_Trockenbau_Qualitäten: 8; Positionsnummer_Text: U100
 | H2 Ebene +1 | WI-IW | 1163Wa 0813718659 | yes | Codetext | m² | Trockenbauarbeiten | Wand | Installationswand | WI-IW | 0 | A | 3.75 | 1163HWa0813718658 | NEW | no | no | 0 | 0 | no | 52 | no | Codetext | AllplanAttributes - ash_W_Trockenbau_Qualitäten: 16; Positionsnummer_Text: U100
 | H2 Ebene +1 | Installationsraum | 1163Wa 0812533133 | yes | Codetext | m² | Trockenbauarbeiten | Wand | Installationswand | Installationsraum | 0 | A | 3.75 | 1163HWa0812533113 | NEW | no | no | 0 | 0 | no | 0 | no | Codetext | AllplanAttributes - Positionsnummer_Text: U100
 | H2 Ebene +1 | WI-VS | 1163Wa 0812533135 | yes | Codetext | m² | Trockenbauarbeiten | Wand | Installationswand | WI-VS | 0 | A | 3.75 | 1163HWa0812533113 | NEW | no | no | 0 | 0 | no | 0 | no | Codetext | AllplanAttributes - W_Deckenanschluss: Gleitender Deckenanschluss Fall 01; ash_W_Trockenbau_Qualitäten: 5; Positionsnummer_Text: U100
 | H2 Ebene +1 | Installationsraum | 1163Wa 0812533131 | yes | Codetext | m² | Trockenbauarbeiten | Wand | Installationswand | Installationsraum | 0 | A | 3.75 | 1163HWa0812533112 | NEW |  | no | 0 | 0 | no | 0 | no | Codetext | AllplanAttributes - Positionsnummer_Text: U100
 | H2 Ebene +1 | WI-VS | 1163Wa 0812533139 | yes | Codetext | m² | Trockenbauarbeiten | Wand | Installationswand | WI-VS | 0 | A | 3.75 | 1163HWa0812533112 | NEW |  | no | 0 | 0 | no | 0 | no | Codetext | AllplanAttributes - W_Deckenanschluss: Gleitender Deckenanschluss Fall 01; ash_W_Trockenbau_Qualitäten: 5; Positionsnummer_Text: U100
 | H2 Ebene +1 | WI-LB | 1163Wa 0814679570 | yes | Codetext | m² | Trockenbauarbeiten | Wand | Innenwand 1-Schalig | WI-LB | 0 | A | 3.75 | 1163HWa0813711600 | NEW |  | no | 0 | 0 | no | 0 | no | Codetext | AllplanAttributes - ash_W_Trockenbau_Qualitäten: 6; Positionsnummer_Text: U100
 | H2 Ebene +1 | WI-LB | 1163Wa 0813711601 | yes | Codetext | m² | Trockenbauarbeiten | Wand | Innenwand 1-Schalig | WI-LB | 0 | A | 3.75 | 1163HWa0813711600 | NEW | no | no | 0 | 0 | no | 0 | no | Codetext | AllplanAttributes - ash_W_Trockenbau_Qualitäten: 8; Positionsnummer_Text: U100
 | H2 Ebene +1 | WI-LB | 1163Wa 0814296851 | yes | Codetext | m² | Trockenbauarbeiten | Wand | Innenwand 1-Schalig | WI-LB | 0 | A | 3.75 | 1163HWa0812425462 | NEW | no | no | REI 60-A1 - D,s2-d0 +A1 | 0 | no | 47 | no | Codetext | AllplanAttributes - ash_W_Trockenbau_Qualitäten: 1b; Positionsnummer_Text: U100
 | H2 Ebene +1 | WI-IW | 1163Wa 0814620779 | yes | Codetext | m² | Trockenbauarbeiten | Wand | Installationswand | WI-IW | 0 | A | 3.75 | 1163HWa0812534066 | NEW | no | no | REI 30-A1 - D,s2-d0 +A1 | 0 | no | 0 | no | Codetext | AllplanAttributes - ash_W_Trockenbau_Qualitäten: 11; Positionsnummer_Text: U100
 | H2 Ebene +1 | Installationsraum | 1163Wa 0812534077 | yes | Codetext | m² | Trockenbauarbeiten | Wand | Installationswand | Installationsraum | 0 | A | 3.75 | 1163HWa0812534066 | NEW | no | no | 0 | 0 | no | 0 | no | Codetext | AllplanAttributes - Positionsnummer_Text: U100
 | H2 Ebene +1 | WI-IW | 1163Wa 0812534075 | yes | Codetext | m² | Trockenbauarbeiten | Wand | Installationswand | WI-IW | 0 | A | 3.75 | 1163HWa0812534066 | NEW | no | no | 0 | 0 | no | 0 | no | Codetext | AllplanAttributes - W_Deckenanschluss: Gleitender Deckenanschluss Fall 01; ash_W_Trockenbau_Qualitäten: 11; Positionsnummer_Text: U100
 | H2 Ebene +1 | Installationsraum | 1163Wa 0812437629 | yes | Codetext | m² | Trockenbauarbeiten | Wand | Installationswand | Installationsraum | 0 | A | 3.75 | 1163HWa0812430732 | NEW |  | no | 0 | 0 | no | 0 | no | Codetext | AllplanAttributes - Positionsnummer_Text: U100
 | H2 Ebene +1 | WI-VS | 1163Wa 0812437623 | yes | Codetext | m² | Trockenbauarbeiten | Wand | Installationswand | WI-VS | 0 | A | 3.75 | 1163HWa0812430732 | NEW |  | no | 0 | 0 | no | 0 | no | Codetext | AllplanAttributes - W_Deckenanschluss: Gleitender Deckenanschluss Fall 01; ash_W_Trockenbau_Qualitäten: 2; Positionsnummer_Text: U100
 | H2 Ebene +1 | Installationsraum | 1163Wa 0812437235 | yes | Codetext | m² | Trockenbauarbeiten | Wand | Installationswand | Installationsraum | 0 | A | 3.75 | 1163HWa0812425828 | NEW | no | no | 0 | 0 | no | 0 | no | Codetext | AllplanAttributes - Ortscode_Geschoßbezeichnung: E01; Positionsnummer_Text: U100
 | H2 Ebene +1 | WI-VS | 1163Wa 0812437241 | yes | Codetext | m² | Trockenbauarbeiten | Wand | Installationswand | WI-VS | 0 | A | 3.75 | 1163HWa0812425828 | NEW | no | no | 0 | 0 | no | 0 | no | Codetext | AllplanAttributes - Ortscode_Geschoßbezeichnung: E01; W_Deckenanschluss: Gleitender Deckenanschluss Fall 01; ash_W_Trockenbau_Qualitäten: 2; Positionsnummer_Text: U100
 | H2 Ebene +1 | Installationsraum | 1163Wa 0812437666 | yes | Codetext | m² | Trockenbauarbeiten | Wand | Installationswand | Installationsraum | 0 | A | 3.75 | 1163HWa0812425826 | NEW | no | no | 0 | 0 | no | 0 | no | Codetext | AllplanAttributes - Ortscode_Geschoßbezeichnung: E01; Positionsnummer_Text: U100
 | H2 Ebene +1 | WI-VS | 1163Wa 0812437664 | yes | Codetext | m² | Trockenbauarbeiten | Wand | Installationswand | WI-VS | 0 | A | 3.75 | 1163HWa0812425826 | NEW | no | no | 0 | 0 | no | 0 | no | Codetext | AllplanAttributes - Ortscode_Geschoßbezeichnung: E01; W_Deckenanschluss: Gleitender Deckenanschluss Fall 01; ash_W_Trockenbau_Qualitäten: 2; Positionsnummer_Text: U100
 | H2 Ebene +1 | WI-IW | 1163Wa 0812437662 | yes | Codetext | m² | Trockenbauarbeiten | Wand | Installationswand | WI-IW | 0 | A | 3.75 | 1163HWa0812425829 | NEW | no | no | 0 | 0 | no | 0 | no | Codetext | AllplanAttributes - W_Deckenanschluss: Gleitender Deckenanschluss Fall 01; ash_W_Trockenbau_Qualitäten: 11; Positionsnummer_Text: U100
 | H2 Ebene +1 | Installationsraum | 1163Wa 0812437660 | yes | Codetext | m² | Trockenbauarbeiten | Wand | Installationswand | Installationsraum | 0 | A | 3.75 | 1163HWa0812425829 | NEW | no | no | 0 | 0 | no | 0 | no | Codetext | AllplanAttributes - Positionsnummer_Text: U100
 | H2 Ebene +1 | WI-IW | 1163Wa 0812437238 | yes | Codetext | m² | Trockenbauarbeiten | Wand | Installationswand | WI-IW | 0 | A | 3.75 | 1163HWa0812425829 | NEW | no | no | 0 | 0 | no | 0 | no | Codetext | AllplanAttributes - W_Deckenanschluss: Gleitender Deckenanschluss Fall 01; ash_W_Trockenbau_Qualitäten: 11; Positionsnummer_Text: U100
 | H2 Ebene +1 | WI-LB | 1163Wa 0812655406 | yes | Codetext | m² | Trockenbauarbeiten | Wand | Innenwand 1-Schalig | WI-LB | 0 | A | 3.75 | 1163HWa0812655284 | NEW | no | no | REI 60-A1 - D,s2-d0 /A1 | 0 | no | 0 | no | Codetext | AllplanAttributes - ash_W_Trockenbau_Qualitäten: 16; Positionsnummer_Text: U100
 | H2 Ebene +1 | WI-HW 60 | 1163Wa 0814105800 | yes | Codetext | m² | Zimmer- und Holzbauarbeiten | Wand | Innenwand 1-Schalig | WI-HW 60 | 0 | A | 3.75 | 1163HWa0812655284 | NEW | yes | no | REI 60-A1 - D,s2-d0 /A1 | 0 | no | 0 | no | Codetext | AllplanAttributes - ash W_laufende Nr. Statik: 3 (W 3.0); Positionsnummer_Text: U100
 | H2 Ebene +1 | Installationsraum | 1163Wa 0812438792 | yes | Codetext | m² | Trockenbauarbeiten | Wand | Installationswand | Installationsraum | 0 | A | 3.75 | 1163HWa0812438779 | NEW |  | no | 0 | 0 | no | 0 | no | Codetext | AllplanAttributes - Positionsnummer_Text: U100
 | H2 Ebene +1 | WI-VS | 1163Wa 0812438794 | yes | Codetext | m² | Trockenbauarbeiten | Wand | Installationswand | WI-VS | 0 | A | 3.75 | 1163HWa0812438779 | NEW |  | no | 0 | 0 | no | 0 | no | Codetext | AllplanAttributes - W_Deckenanschluss: Gleitender Deckenanschluss Fall 01; ash_W_Trockenbau_Qualitäten: 18; Positionsnummer_Text: U100
 | H2 Ebene +1 | Installationsraum | 1163Wa 0812816616 | yes | Codetext | m² | Trockenbauarbeiten | Wand | Installationswand | Installationsraum | 0 | A | 3.75 | 1163HWa0812816615 | NEW | no | no | 0 | 0 | no | 0 | no | Codetext | AllplanAttributes - Positionsnummer_Text: U100
 | H2 Ebene +1 | WI-IW | 1163Wa 0812816617 | yes | Codetext | m² | Trockenbauarbeiten | Wand | Installationswand | WI-IW | 0 | A | 3.75 | 1163HWa0812816615 | NEW | no | no | 0 | 0 | no | 0 | no | Codetext | AllplanAttributes - W_Deckenanschluss: Gleitender Deckenanschluss Fall 01; ash_W_Trockenbau_Qualitäten: 2; Positionsnummer_Text: U100
 | H2 Ebene +1 | WI-LB | 1163Wa 0813711655 | yes | Codetext | m² | Trockenbauarbeiten | Wand | Innenwand 1-Schalig | WI-LB | 0 | A | 3.75 | 1163HWa0813711653 | NEW | no | no | 0 | 0 | no | 0 | no | Codetext | AllplanAttributes - ash_W_Trockenbau_Qualitäten: 8; Positionsnummer_Text: U100
 | H2 Ebene +1 | WI-LB | 1163Wa 0812441691 | yes | Codetext | m² | Trockenbauarbeiten | Wand | Innenwand 1-Schalig | WI-LB | 0 | A | 3.75 | 1163HWa0812440885 | NEW | no | no | 0 | 0 | no | 0 | no | Codetext | AllplanAttributes - Ortscode_Geschoßbezeichnung: E01; W_Deckenanschluss: Gleitender Deckenanschluss Fall 03; ash_W_Trockenbau_Qualitäten: 10a; Positionsnummer_Text: U100
 | H2 Ebene +1 | Installationsraum | 1163Wa 0814521708 | yes | Codetext | m² | Trockenbauarbeiten | Wand | Installationswand | Installationsraum | 0 | A | 3.75 | 1163HWa0812463423 | NEW | no | no | 0 | 0 | no | 0 | no | Codetext | AllplanAttributes - Positionsnummer_Text: U100
 | H2 Ebene +1 | WI-VS | 1163Wa 0814521709 | yes | Codetext | m² | Trockenbauarbeiten | Wand | Installationswand | WI-VS | 0 | A | 3.75 | 1163HWa0812463423 | NEW | no | no | 0 | 0 | no | 0 | no | Codetext | AllplanAttributes - W_Deckenanschluss: Gleitender Deckenanschluss Fall 01; Positionsnummer_Text: U100
 | H2 Ebene +1 | WI-LB | 1163Wa 0812441621 | yes | Codetext | m² | Trockenbauarbeiten | Wand | Innenwand 1-Schalig | WI-LB | 0 | A | 3.75 | 1163HWa0812440877 | NEW | no | no | 0 | 0 | no | 0 | no | Codetext | AllplanAttributes - W_Deckenanschluss: Gleitender Deckenanschluss Fall 03; ash_W_Trockenbau_Qualitäten: 1b; Positionsnummer_Text: U100
 | H2 Ebene +1 | WI-LB | 1163Wa 0812441640 | yes | Codetext | m² | Trockenbauarbeiten | Wand | Innenwand 1-Schalig | WI-LB | 0 | A | 3.75 | 1163HWa0812440884 | NEW | no | no | 0 | 0 | no | 0 | no | Codetext | AllplanAttributes - Ortscode_Geschoßbezeichnung: E01; W_Deckenanschluss: Gleitender Deckenanschluss Fall 03; ash_W_Trockenbau_Qualitäten: 10a; Positionsnummer_Text: U100
 | H2 Ebene +1 | WI-LB | 1163Wa 0812441654 | yes | Codetext | m² | Trockenbauarbeiten | Wand | Innenwand 1-Schalig | WI-LB | 0 | A | 3.75 | 1163HWa0812440930 | NEW | no | no | 0 | 0 | no | 47 | no | Codetext | AllplanAttributes - Ortscode_Geschoßbezeichnung: E01; W_Deckenanschluss: Gleitender Deckenanschluss Fall 03; ash_W_Trockenbau_Qualitäten: 1c; Positionsnummer_Text: U100
 | H2 Ebene +1 | WI-LB | 1163Wa 0812442079 | yes | Codetext | m² | Trockenbauarbeiten | Wand | Innenwand 1-Schalig | WI-LB | 0 | A | 3.75 | 1163HWa0812428818 | NEW | no | no | REI 60-A1 - D,s2-d0 /A1 | 0 | no | 0 | no | Codetext | AllplanAttributes - Ortscode_Geschoßbezeichnung: E01; ash_W_Trockenbau_Qualitäten: 13; Positionsnummer_Text: U100
 | H2 Ebene +1 | WI-LB | 1163Wa 0812440861 | yes | Codetext | m² | Trockenbauarbeiten | Wand | Innenwand 1-Schalig | WI-LB | 0 | A | 3.75 | 1163HWa0812434689 | NEW | no | no | 0 | 0 | no | 0 | no | Codetext | AllplanAttributes - W_Deckenanschluss: Gleitender Deckenanschluss Fall 01; ash_W_Trockenbau_Qualitäten: 12a; Positionsnummer_Text: U100
 | H2 Ebene +1 | WI-LW 60 | 1163Wa 0812500751 | yes | Codetext | m² | Trockenbauarbeiten | Wand | Innenwand 1-Schalig | WI-LW 60 | 0 | A | 3.75 | 1163HWa0812500638 | NEW | yes | no | REI 60-A1 - D,s2-d0 +A1 | 0 | no | 0 | no | Codetext | AllplanAttributes - W_Deckenanschluss: Gleitender Deckenanschluss Fall 01; ash_W_Trockenbau_Qualitäten: 12b; Positionsnummer_Text: U100
 | H2 Ebene +1 | WI-LB | 1163Wa 0812443166 | yes | Codetext | m² | Trockenbauarbeiten | Wand | Innenwand 1-Schalig | WI-LB | 0 | A | 3.75 | 1163HWa0812425462 | NEW | no | no | REI 60-A1 - D,s2-d0 +A1 | 0 | no | 47 | no | Codetext | AllplanAttributes - Ortscode_Geschoßbezeichnung: E01; ash_W_Trockenbau_Qualitäten: 1b; Positionsnummer_Text: U100
 | H2 Ebene +1 | WI-LB | 1163Wa 0812443009 | yes | Codetext | m² | Trockenbauarbeiten | Wand | Innenwand 1-Schalig | WI-LB | 0 | A | 3.75 | 1163HWa0812441874 | NEW |  | no | REI 60-A1 - D,s2-d0 +A1 | 0 | no | 0 | no | Codetext | AllplanAttributes - Ortscode_Geschoßbezeichnung: E01; W_Deckenanschluss: Gleitender Deckenanschluss Fall 01; ash_W_Trockenbau_Qualitäten: 10b; Positionsnummer_Text: U100
 | H2 Ebene +1 | WI-LB | 1163Wa 0812442706 | yes | Codetext | m² | Trockenbauarbeiten | Wand | Innenwand 1-Schalig | WI-LB | 0 | A | 3.75 | 1163HWa0812440867 | NEW | no | no | REI 60-A1 - D,s2-d0 +A1 | 0 | no | 0 | no | Codetext | AllplanAttributes - Ortscode_Geschoßbezeichnung: E01; W_Deckenanschluss: Gleitender Deckenanschluss Fall 01; ash_W_Trockenbau_Qualitäten: 1b; Positionsnummer_Text: U100
 | H2 Ebene +1 | WI-LB | 1163Wa 0814484139 | yes | Codetext | m² | Trockenbauarbeiten | Wand | Innenwand 1-Schalig | WI-LB | 0 | A | 3.75 | 1163HWa0812442703 | NEW |  | no | REI 60-A1 - D,s2-d0 +A1 | 0 | no | 0 | no | Codetext | AllplanAttributes - W_Deckenanschluss: Gleitender Deckenanschluss Fall 01; ash_W_Trockenbau_Qualitäten: 1a; Positionsnummer_Text: U100
 | H2 Ebene +1 | WI-LB | 1163Wa 0814490057 | yes | Codetext | m² | Trockenbauarbeiten | Wand | Innenwand 1-Schalig | WI-LB | 0 | A | 3.75 | 1163HWa0812443364 | NEW | no | no | REI 30-A1 - D,s2-d0 +A1 | 0 | no | 47 | no | Codetext | AllplanAttributes - W_Deckenanschluss: Gleitender Deckenanschluss Fall 01; ash_W_Trockenbau_Qualitäten: 1a; Positionsnummer_Text: U100
 | H2 Ebene +1 | WI-LB | 1163Wa 0812444170 | yes | Codetext | m² | Trockenbauarbeiten | Wand | Innenwand 1-Schalig | WI-LB | 0 | A | 3.75 | 1163HWa0812428824 | NEW |  | no | 0 | 0 | no | 47 | no | Codetext | AllplanAttributes - W_Deckenanschluss: Gleitender Deckenanschluss Fall 01; ash_W_Trockenbau_Qualitäten: 1e; Positionsnummer_Text: U100
 | H2 Ebene +1 | WI-IW | 1163Wa 0812464676 | yes | Codetext | m² | Trockenbauarbeiten | Wand | Installationswand | WI-IW | 0 | A | 3.75 | 1163HWa0812464675 | NEW |  | no | 0 | 0 | no | 0 | no | Codetext | AllplanAttributes - W_Deckenanschluss: Gleitender Deckenanschluss Fall 01; ash_W_Trockenbau_Qualitäten: 18; Positionsnummer_Text: U100
 | H2 Ebene +1 | WI-LB | 1163Wa 0812442525 | yes | Codetext | m² | Trockenbauarbeiten | Wand | Innenwand 1-Schalig | WI-LB | 0 | A | 3.75 | 1163HWa0812435292 | NEW |  | no | 0 | 0 | no | 52 | no | Codetext | AllplanAttributes - Ortscode_Geschoßbezeichnung: E01; W_Deckenanschluss: Gleitender Deckenanschluss Fall 01; ash_W_Trockenbau_Qualitäten: 1b; Positionsnummer_Text: U100
 | H2 Ebene +1 | WI-IW | 1163Wa 0812464251 | yes | Codetext | m² | Trockenbauarbeiten | Wand | Installationswand | WI-IW | 0 | A | 3.75 | 1163HWa0812464250 | NEW |  | no | 0 | 0 | no | 0 | no | Codetext | AllplanAttributes - W_Deckenanschluss: Gleitender Deckenanschluss Fall 01; ash_W_Trockenbau_Qualitäten: 18; Positionsnummer_Text: U100
 | H2 Ebene +1 | Installationsraum | 1163Wa 0812464252 | yes | Codetext | m² | Trockenbauarbeiten | Wand | Installationswand | Installationsraum | 0 | A | 3.75 | 1163HWa0812464250 | NEW |  | no | 0 | 0 | no | 0 | no | Codetext | AllplanAttributes - Positionsnummer_Text: U100
 | H2 Ebene +1 | WI-LB | 1163Wa 0814705832 | yes | Codetext | m² | Trockenbauarbeiten | Wand | Innenwand 1-Schalig | WI-LB | 0 | A | 3.75 | 1163HWa0814107885 | NEW |  | no | 0 | 0 | no | 47 | no | Codetext | AllplanAttributes - W_Deckenanschluss: Gleitender Deckenanschluss Fall 01; ash_W_Trockenbau_Qualitäten: 1d; Positionsnummer_Text: U100
 | H2 Ebene +1 | WI-LB | 1163Wa 0814705941 | yes | Codetext | m² | Trockenbauarbeiten | Wand | Innenwand 1-Schalig | WI-LB | 0 | A | 3.75 | 1163HWa0814107885 | NEW |  | no | 0 | 0 | no | 47 | no | Codetext | AllplanAttributes - W_Deckenanschluss: Gleitender Deckenanschluss Fall 01; ash_W_Trockenbau_Qualitäten: 1b; Positionsnummer_Text: U100
 | H2 Ebene +1 | WI-LW 60 | 1163Wa 0814007554 | yes | Codetext | m² | Trockenbauarbeiten | Wand | Innenwand 1-Schalig | WI-LW 60 | 0 | A | 3.75 | 1163HWa0814007421 | NEW | yes | no | REI 60-A1 - D,s2-d0 +A1 | 0 | no | 47 | no | Codetext | AllplanAttributes - W_Deckenanschluss: Gleitender Deckenanschluss Fall 01; ash_W_Trockenbau_Qualitäten: 12b; Positionsnummer_Text: U100
 | H2 Ebene +1 | WI-LB | 1163Wa 0814683520 | yes | Codetext | m² | Trockenbauarbeiten | Wand | Innenwand 1-Schalig | WI-LB | 0 | A | 3.75 | 1113HWa0812959982 | NEW | no | no | REI 60-A1 - D,s2-d0 /A1 | 0 | no | 0 | no | Codetext | AllplanAttributes - ash_W_Trockenbau_Qualitäten: 15; Sicherheitsklasse: -; Positionsnummer_Text: U100
 | H2 Ebene +1 | WI-HW 60 | 1163Wa 0814683524 | yes | Codetext | m² | Zimmer- und Holzbauarbeiten | Wand | Innenwand 1-Schalig | WI-HW 60 | 0 | A | 3.75 | 1163HWa0812434662 | NEW | yes | no | REI 60-A1 - D,s2-d0 +A1 | 0 | no | 47 | no | Codetext | AllplanAttributes - ash W_laufende Nr. Statik: 3 (W 3.0); Positionsnummer_Text: U100
 | H2 Ebene +1 | Installationsraum | 1163Wa 0814683521 | yes | Codetext | m² | Trockenbauarbeiten | Wand | Innenwand 1-Schalig | Installationsraum | 0 | A | 0 | 1113HWa0812434427 | NEW | no | no | 0 | 0 | no | 0 | no | Codetext | AllplanAttributes - Sicherheitsklasse: -; Positionsnummer_Text: U100
 | H2 Ebene +1 | WI-LB | 1163Wa 0814683522 | yes | Codetext | m² | Trockenbauarbeiten | Wand | Innenwand 1-Schalig | WI-LB | 0 | A | 3.75 | 1163HWa0812434662 | NEW | no | no | REI 60-A1 - D,s2-d0 /A1 | 0 | no | 0 | no | Codetext | AllplanAttributes - ash_W_Trockenbau_Qualitäten: 15; Positionsnummer_Text: U100
 | H2 Ebene +1 | WI-LB | 1163Wa 0814705891 | yes | Codetext | m² | Trockenbauarbeiten | Wand | Innenwand 1-Schalig | WI-LB | 0 | A | 3.75 | 1163HWa0814107885 | NEW | no | no | 0 | 0 | no | 47 | no | Codetext | AllplanAttributes - W_Deckenanschluss: Gleitender Deckenanschluss Fall 01; ash_W_Trockenbau_Qualitäten: 1a; Positionsnummer_Text: U100
 | H2 Ebene +1 | WI-LB | 1163Wa 0814705865 | yes | Codetext | m² | Trockenbauarbeiten | Wand | Innenwand 1-Schalig | WI-LB | 0 | A | 3.75 | 1163HWa0814107885 | NEW | no | no | 0 | 0 | no | 47 | no | Codetext | AllplanAttributes - W_Deckenanschluss: Gleitender Deckenanschluss Fall 01; ash_W_Trockenbau_Qualitäten: 8; Positionsnummer_Text: U100
 | H2 Ebene +1 | WI-LB | 1163Wa 0814611776 | yes | Codetext | m² | Trockenbauarbeiten | Wand | Innenwand 1-Schalig | WI-LB | 0 | A | 3.75 | 1163HWa0812428824 | NEW |  | no | 0 | 0 | no |  | no | Codetext | AllplanAttributes - W_Deckenanschluss: Gleitender Deckenanschluss Fall 01; ash_W_Trockenbau_Qualitäten: 18; Positionsnummer_Text: U100
 | H2 Ebene +1 | WI-LW 60 | 1163Wa 0813982065 | yes |  | m² | Trockenbauarbeiten | Wand | Innenwand 1-Schalig | WI-LW 60 |  |  | 3.75 | 1163HWa0813981823 | NEW | yes | no | REI-M 60-D,s2,d0 + A1 |  |  | 47 | AllplanAttributes - ash_W_Trockenbau_Qualitäten: 12a; Positionsnummer_Text: U100
 | H2 Ebene +1 | WI-IW | 1163Wa 0814706665 | yes | Codetext | m² | Trockenbauarbeiten | Wand | Installationswand | WI-IW | 0 | A | 3.75 | 1163HWa0812464233 | NEW |  | no | 0 | 0 | no | 0 | no | Codetext | AllplanAttributes - W_Deckenanschluss: Gleitender Deckenanschluss Fall 01; ash_W_Trockenbau_Qualitäten: 16; Positionsnummer_Text: U100
 | H2 Ebene +1 | Installationsraum | 1163Wa 0814706666 | yes | Codetext | m² | Trockenbauarbeiten | Wand | Installationswand | Installationsraum | 0 | A | 3.75 | 1163HWa0812464233 | NEW |  | no | 0 | 0 | no | 0 | no | Codetext | AllplanAttributes - Positionsnummer_Text: U100
 | H2 Ebene +1 | WI-LW 60 | 1163Wa 0814705917 | yes | Codetext | m² | Trockenbauarbeiten | Wand | Innenwand 1-Schalig | WI-LW 60 | 0 | A | 3.75 | 1163HWa0812531522 | NEW | yes | no | REI 60-A1 - D,s2-d0 +A1 | 0 | no | 47 | no | Codetext | AllplanAttributes - W_Deckenanschluss: Gleitender Deckenanschluss Fall 01; ash_W_Trockenbau_Qualitäten: 4; Positionsnummer_Text: U100
 | H2 Ebene +1 | WI-LB | 1163Wa 0814706082 | yes | Codetext | m² | Trockenbauarbeiten | Wand | Innenwand 1-Schalig | WI-LB | 0 | A | 3.75 | 1163HWa0814107885 | NEW |  | no | 0 | 0 | no | 47 | no | Codetext | AllplanAttributes - W_Deckenanschluss: Gleitender Deckenanschluss Fall 01; ash_W_Trockenbau_Qualitäten: 1d; Positionsnummer_Text: U100
 | H2 Ebene +1 | WI-IW | 1163Wa 0814706640 | yes | Codetext | m² | Trockenbauarbeiten | Wand | Installationswand | WI-IW | 0 | A | 3.75 | 1163HWa0812464233 | NEW |  | no | 0 | 0 | no | 0 | no | Codetext | AllplanAttributes - W_Deckenanschluss: Gleitender Deckenanschluss Fall 01; ash_W_Trockenbau_Qualitäten: 16; Positionsnummer_Text: U100
 | H2 Ebene +1 | Installationsraum | 1163Wa 0814706641 | yes | Codetext | m² | Trockenbauarbeiten | Wand | Installationswand | Installationsraum | 0 | A | 3.75 | 1163HWa0812464233 | NEW |  | no | 0 | 0 | no | 0 | no | Codetext | AllplanAttributes - Positionsnummer_Text: U100
 | H2 Ebene +1 | WI-IW | 1163Wa 0814706302 | yes | Codetext | m² | Trockenbauarbeiten | Wand | Installationswand | WI-IW | 0 | A | 3.75 | 1163HWa0812464233 | NEW |  | no | 0 | 0 | no | 0 | no | Codetext | AllplanAttributes - W_Deckenanschluss: Gleitender Deckenanschluss Fall 01; ash_W_Trockenbau_Qualitäten: 18; Positionsnummer_Text: U100
 | H2 Ebene +1 | Installationsraum | 1163Wa 0814706303 | yes | Codetext | m² | Trockenbauarbeiten | Wand | Installationswand | Installationsraum | 0 | A | 3.75 | 1163HWa0812464233 | NEW |  | no | 0 | 0 | no | 0 | no | Codetext | AllplanAttributes - Positionsnummer_Text: U100
 | H2 Ebene +1 | WI-LB | 1163Wa 0812439619 | yes | Codetext | m² | Trockenbauarbeiten | Wand | Innenwand 1-Schalig | WI-LB | 0 | A | 3.75 | 1163HWa0812430481 | NEW |  | no | REI 60-A1 - D,s2-d0 +A1 | 0 | no | 47 | no | Codetext | AllplanAttributes - Ortscode_Geschoßbezeichnung: E01; W_Deckenanschluss: Gleitender Deckenanschluss Fall 01; ash_W_Trockenbau_Qualitäten: 1b; Positionsnummer_Text: U100
 | H2 Ebene +1 | WI-LW 60 | 1163Wa 0812508669 | yes | Codetext | m² | Trockenbauarbeiten | Wand | Innenwand 1-Schalig | WI-LW 60 | 0 | A | 3.75 | 1163HWa0812508668 | NEW | yes | no | REI 60-A1 - D,s2-d0 +A1 | 0 | no | 0 | no | Codetext | AllplanAttributes - W_Deckenanschluss: Gleitender Deckenanschluss Fall 01; ash_W_Trockenbau_Qualitäten: 12b; Positionsnummer_Text: U100
 | H2 Ebene +1 | WI-IW | 1163Wa 0813714408 | yes | Codetext | m² | Trockenbauarbeiten | Wand | Installationswand | WI-IW | 0 | A | 3.75 | 1163HWa0812435319 | NEW |  | no | 0 | 0 | no | 47 | no | Codetext | AllplanAttributes - W_Deckenanschluss: Gleitender Deckenanschluss Fall 01; ash_W_Trockenbau_Qualitäten: 14; Positionsnummer_Text: U100
 | H2 Ebene +1 | Installationsraum | 1163Wa 0814594536 | yes | Codetext | m² | Trockenbauarbeiten | Wand | Installationswand | Installationsraum | 0 | A | 3.75 | 1163HWa0812435319 | NEW |  | no | 0 | 0 | no | 0 | no | Codetext | AllplanAttributes - Positionsnummer_Text: U100
 | H2 Ebene +1 | WI-IW | 1163Wa 0814594537 | yes | Codetext | m² | Trockenbauarbeiten | Wand | Installationswand | WI-IW | 0 | A | 3.75 | 1163HWa0812435319 | NEW |  | no | 0 | 0 | no | 47 | no | Codetext | AllplanAttributes - W_Deckenanschluss: Gleitender Deckenanschluss Fall 01; ash_W_Trockenbau_Qualitäten: 14; Positionsnummer_Text: U100
 | H2 Ebene +1 | WI-LB | 1163Wa 0812446900 | yes | Codetext | m² | Trockenbauarbeiten | Wand | Innenwand 1-Schalig | WI-LB | 0 | A | 3.75 | 1163HWa0812433353 | NEW |  | no | 0 | 0 | no | 0 | no | Codetext | AllplanAttributes - Ortscode_Geschoßbezeichnung: E01; W_Deckenanschluss: Gleitender Deckenanschluss Fall 01; ash_W_Trockenbau_Qualitäten: 1b; Positionsnummer_Text: U100
 | H2 Ebene +1 | WI-LB | 1163Wa 0812833408 | yes | Codetext | m² | Trockenbauarbeiten | Wand | Innenwand 1-Schalig | WI-LB | 0 | A | 3.75 | 1163HWa0812833349 | NEW |  | no | 0 | 0 | no | 52 | no | Codetext | AllplanAttributes - Ortscode_Geschoßbezeichnung: E01; W_Deckenanschluss: Gleitender Deckenanschluss Fall 01; ash_W_Trockenbau_Qualitäten: 1b; Positionsnummer_Text: U100
 | H2 Ebene +1 | WI-IW | 1163Wa 0812464601 | yes | Codetext | m² | Trockenbauarbeiten | Wand | Installationswand | WI-IW | 0 | A | 3.75 | 1163HWa0812464600 | NEW |  | no | 0 | 0 | no | 0 | no | Codetext | AllplanAttributes - W_Deckenanschluss: Gleitender Deckenanschluss Fall 01; ash_W_Trockenbau_Qualitäten: 18; Positionsnummer_Text: U100
 | H2 Ebene +1 | Installationsraum | 1163Wa 0812464602 | yes | Codetext | m² | Trockenbauarbeiten | Wand | Installationswand | Installationsraum | 0 | A | 3.75 | 1163HWa0812464600 | NEW |  | no | 0 | 0 | no | 0 | no | Codetext | AllplanAttributes - Positionsnummer_Text: U100
Promat / BS | H2 Ebene +1 | WI-LB | 1163Wa 0814615315 | yes | Codetext | m² | Trockenbauarbeiten | Wand | Promat / BS | WI-LB | 0 | A | 3.75 | 1163HWa0812835805 | NEW | no | no |  | 0 | no | 0 | no | Codetext | AllplanAttributes - ash_W_Trockenbau_Qualitäten: 1a; Positionsnummer_Text: U100
 | H2 Ebene +1 | Installationsraum | 1163Wa 0812838161 | yes | Codetext | m² | Trockenbauarbeiten | Wand | Installationswand | Installationsraum | 0 | A | 3.75 | 1163HWa0812838160 | NEW | no | no | 0 | 0 | no | 0 | no | Codetext | AllplanAttributes - Positionsnummer_Text: U100
 | H2 Ebene +1 | WI-VS | 1163Wa 0812838162 | yes | Codetext | m² | Trockenbauarbeiten | Wand | Installationswand | WI-VS | 0 | A | 3.75 | 1163HWa0812838160 | NEW | no | no | 0 | 0 | no | 0 | no | Codetext | AllplanAttributes - W_Deckenanschluss: Gleitender Deckenanschluss Fall 03; ash_W_Trockenbau_Qualitäten: 21; Positionsnummer_Text: U100
 | H2 Ebene +1 | WI-LB | 1163Wa 0813929020 | yes | Codetext | m² | Trockenbauarbeiten | Wand | Innenwand 1-Schalig | WI-LB | 0 | A | 3.75 | 1163HWa0813928878 | NEW | no | no | 0 | 0 | no | 0 | no | Codetext | AllplanAttributes - W_Deckenanschluss: Gleitender Deckenanschluss Fall 01; ash_W_Trockenbau_Qualitäten: 12a; Positionsnummer_Text: U100
 | H2 Ebene +1 | WI-LB | 1163Wa 0814491287 | yes | Codetext | m² | Trockenbauarbeiten | Wand | Innenwand 1-Schalig | WI-LB | 0 | A | 3.75 | 1163HWa0812430876 | NEW |  | no | REI 60-A1 - D,s2-d0 +A1 | 0 | no | 0 | no | Codetext | AllplanAttributes - W_Deckenanschluss: Gleitender Deckenanschluss Fall 01; ash_W_Trockenbau_Qualitäten: 1a; Positionsnummer_Text: U100
 | H2 Ebene +1 | WI-LB | 1163Wa 0812437372 | yes | Codetext | m² | Trockenbauarbeiten | Wand | Innenwand 1-Schalig | WI-LB | 0 | A | 3.75 | 1163HWa0812425463 | NEW | no | no | 0 | 0 | no | 0 | no | Codetext | AllplanAttributes - W_Deckenanschluss: Gleitender Deckenanschluss Fall 01; ash_W_Trockenbau_Qualitäten: 12b; Positionsnummer_Text: U100
 | H2 Ebene +1 | WI-LB | 1163Wa 0814619421 | yes | Codetext | m² | Trockenbauarbeiten | Wand | Innenwand 1-Schalig | WI-LB | 0 | A | 3.75 | 1163HWa0812430876 | NEW |  | no | REI 60-A1 - D,s2-d0 +A1 | 0 | no | 0 | no | Codetext | AllplanAttributes - W_Deckenanschluss: Gleitender Deckenanschluss Fall 01; ash_W_Trockenbau_Qualitäten: 1b; Positionsnummer_Text: U100
 | H2 Ebene +1 | WI-LB | 1163Wa 0812440268 | yes | Codetext | m² | Trockenbauarbeiten | Wand | Innenwand 1-Schalig | WI-LB | 0 | A | 3.75 | 1163HWa0812438825 | NEW | no | no | 0 | 0 | no | 0 | no | Codetext | AllplanAttributes - W_Deckenanschluss: Gleitender Deckenanschluss Fall 01; ash_W_Trockenbau_Qualitäten: 12b; Positionsnummer_Text: U100
 | H2 Ebene +1 | WI-LB | 1163Wa 0812444049 | yes | Codetext | m² | Trockenbauarbeiten | Wand | Innenwand 1-Schalig | WI-LB | 0 | A | 3.75 | 1163HWa0812425617 | NEW | no | no | REI 60-A1 - D,s2-d0 +A1 | 0 | no | 47 | no | Codetext | AllplanAttributes - Ortscode_Geschoßbezeichnung: E01; W_Deckenanschluss: Gleitender Deckenanschluss Fall 01; ash_W_Trockenbau_Qualitäten: 1b; Positionsnummer_Text: U100
 | H2 Ebene +1 | WI-LB | 1163Wa 0814758921 | yes | Codetext | m² | Trockenbauarbeiten | Wand | Innenwand 1-Schalig | WI-LB | 0 | A | 3.75 | 1163HWa0812444214 | NEW |  | no | REI 30-A1 - D,s2-d0 +A1 | 0 | no | 47 | no | Codetext | AllplanAttributes - ash_W_Trockenbau_Qualitäten: 6; Sicherheitsklasse: -; Positionsnummer_Text: U100
 | H2 Ebene +1 | WI-LB | 1163Wa 0812840219 | yes | Codetext | m² | Trockenbauarbeiten | Wand | Innenwand 1-Schalig | WI-LB | 0 | A | 3.75 | 1163HWa0812840218 | NEW | no | no | REI 60-A1 - D,s2-d0 /A1 | 0 | no | 0 | no | Codetext | AllplanAttributes - Ortscode_Geschoßbezeichnung: E01; ash_W_Trockenbau_Qualitäten: 9; Positionsnummer_Text: U100
 | H2 Ebene +1 | WI-GKF | 1163Wa 0814477927 | yes | Codetext | m² | Trockenbauarbeiten | Wand | Innenwand 1-Schalig | WI-GKF | 0 | A | 3.75 | 1163HWa0812812420 | NEW | no | no | EI 60-A1 - D,s2,d0 +A1 | 0 | no | 0 | no | Codetext | AllplanAttributes - Positionsnummer_Text: U100
 | H2 Ebene +1 | WI-HW 60 | 1163Wa 0814759282 | yes |  | m² | Zimmer- und Holzbauarbeiten | Wand | Innenwand 1-Schalig | WI-HW 60 |  |  | 3.75 | 1163HWa0812430471 | NEW | no | no | REI-M 60-D,s2,d0 + A1 | AllplanAttributes - ash W_laufende Nr. Statik: 7 (W 6.0-1); Positionsnummer_Text: U100
 | H2 Ebene +1 | WI-GKF | 1163Wa 0814477915 | yes | Codetext | m² | Trockenbauarbeiten | Wand | Innenwand 1-Schalig | WI-GKF | 0 | A | 3.75 | 1163HWa0812812420 | NEW | no | no | EI 60-A1 - D,s2,d0 +A1 | 0 | no | 0 | no | Codetext | AllplanAttributes - Positionsnummer_Text: U100
 | H2 Ebene +1 | WI-HW 60 | 1163Wa 0814759340 | yes |  | m² | Zimmer- und Holzbauarbeiten | Wand | Innenwand 1-Schalig | WI-HW 60 |  |  | 3.75 | 1163HWa0812430471 | NEW | no | no | REI-M 60-D,s2,d0 + A1 | AllplanAttributes - ash W_laufende Nr. Statik: 7 (W 6.0-1); Positionsnummer_Text: U100
 | H2 Ebene +1 | WI-GKF | 1163Wa 0814477905 | yes | Codetext | m² | Trockenbauarbeiten | Wand | Innenwand 1-Schalig | WI-GKF | 0 | A | 3.75 | 1163HWa0812812420 | NEW | no | no | EI 60-A1 - D,s2,d0 +A1 | 0 | no | 0 | no | Codetext | AllplanAttributes - Positionsnummer_Text: U100
 | H2 Ebene +1 | WI-HW 60 | 1163Wa 0814759358 | yes |  | m² | Zimmer- und Holzbauarbeiten | Wand | Innenwand 1-Schalig | WI-HW 60 |  |  | 3.75 | 1163HWa0812430471 | NEW | no | no | REI-M 60-D,s2,d0 + A1 | AllplanAttributes - ash W_laufende Nr. Statik: 7 (W 6.0-1); Positionsnummer_Text: U100
 | H2 Ebene +1 | WI-GKF | 1163Wa 0814759627 | yes | Codetext | m² | Trockenbauarbeiten | Wand | Innenwand 1-Schalig | WI-GKF | 0 | A | 3.75 | 1163HWa0812812420 | NEW | no | no | EI 60-A1 - D,s2,d0 +A1 | 0 | no | 0 | no | Codetext | AllplanAttributes - Positionsnummer_Text: U100
 | H2 Ebene +1 | WI-HW 60 | 1163Wa 0814759628 | yes |  | m² | Zimmer- und Holzbauarbeiten | Wand | Innenwand 1-Schalig | WI-HW 60 |  |  | 3.75 | 1163HWa0812430471 | NEW | no | no | REI-M 60-D,s2,d0 + A1 | AllplanAttributes - ash W_laufende Nr. Statik: 7 (W 6.0-1); Positionsnummer_Text: U100
 | H2 Ebene +1 | WI-GKF | 1163Wa 0814759635 | yes | Codetext | m² | Trockenbauarbeiten | Wand | Innenwand 1-Schalig | WI-GKF | 0 | A | 3.75 | 1163HWa0812812420 | NEW | no | no | EI 60-A1 - D,s2,d0 +A1 | 0 | no | 0 | no | Codetext | AllplanAttributes - Positionsnummer_Text: U100
 | H2 Ebene +1 | WI-HW 60 | 1163Wa 0814759636 | yes |  | m² | Zimmer- und Holzbauarbeiten | Wand | Innenwand 1-Schalig | WI-HW 60 |  |  | 3.75 | 1163HWa0812430471 | NEW | no | no | REI-M 60-D,s2,d0 + A1 | AllplanAttributes - ash W_laufende Nr. Statik: 7 (W 6.0-1); Positionsnummer_Text: U100
 | H2 Ebene +1 | WI-GKF | 1163Wa 0814759652 | yes | Codetext | m² | Trockenbauarbeiten | Wand | Innenwand 1-Schalig | WI-GKF | 0 | A | 3.75 | 1163HWa0812812420 | NEW | no | no | EI 60-A1 - D,s2,d0 +A1 | 0 | no | 0 | no | Codetext | AllplanAttributes - Positionsnummer_Text: U100
 | H2 Ebene +1 | WI-HW 60 | 1163Wa 0814759653 | yes |  | m² | Zimmer- und Holzbauarbeiten | Wand | Innenwand 1-Schalig | WI-HW 60 |  |  | 3.75 | 1163HWa0812430471 | NEW | no | no | REI-M 60-D,s2,d0 + A1 | AllplanAttributes - ash W_laufende Nr. Statik: 7 (W 6.0-1); Positionsnummer_Text: U100
 | H2 Ebene +1 | WI-GKF | 1163Wa 0814759673 | yes | Codetext | m² | Trockenbauarbeiten | Wand | Innenwand 1-Schalig | WI-GKF | 0 | A | 3.75 | 1163HWa0812812420 | NEW | no | no | EI 60-A1 - D,s2,d0 +A1 | 0 | no | 0 | no | Codetext | AllplanAttributes - Positionsnummer_Text: U100
 | H2 Ebene +1 | WI-HW 60 | 1163Wa 0814759674 | yes |  | m² | Zimmer- und Holzbauarbeiten | Wand | Innenwand 1-Schalig | WI-HW 60 |  |  | 3.75 | 1163HWa0812430471 | NEW | no | no | REI-M 60-D,s2,d0 + A1 | AllplanAttributes - ash W_laufende Nr. Statik: 7 (W 6.0-1); Positionsnummer_Text: U100
 | H2 Ebene +1 | WI-GKF | 1163Wa 0814759730 | yes | Codetext | m² | Trockenbauarbeiten | Wand | "BS-Beplankung; 2-fach Gipsfaserplatten" | WI-GKF | 0 | A | 3.75 | 1163HWa0813764687 | NEW | no | no | EI 60-A1 - D,s2,d0 +A1 | 0 | no | 0 | no | Codetext | AllplanAttributes - Positionsnummer_Text: U100
 | H2 Ebene +1 | WI-GKF | 1163Wa 0814759737 | yes | Codetext | m² | Trockenbauarbeiten | Wand | "BS-Beplankung; 2-fach Gipsfaserplatten" | WI-GKF | 0 | A | 3.75 | 1163HWa0813764687 | NEW | no | no | EI 60-A1 - D,s2,d0 +A1 | 0 | no | 0 | no | Codetext | AllplanAttributes - Positionsnummer_Text: U100
 | H2 Ebene +1 | WI-GKF | 1163Wa 0814759763 | yes | Codetext | m² | Trockenbauarbeiten | Wand | "BS-Beplankung; 2-fach Gipsfaserplatten" | WI-GKF | 0 | A | 3.75 | 1163HWa0813764687 | NEW | no | no | EI 60-A1 - D,s2,d0 +A1 | 0 | no | 0 | no | Codetext | AllplanAttributes - Positionsnummer_Text: U100
 | H2 Ebene +1 | WI-GKF | 1163Wa 0814759782 | yes | Codetext | m² | Trockenbauarbeiten | Wand | "BS-Beplankung; 2-fach Gipsfaserplatten" | WI-GKF | 0 | A | 3.75 | 1163HWa0813764687 | NEW | no | no | EI 60-A1 - D,s2,d0 +A1 | 0 | no | 0 | no | Codetext | AllplanAttributes - Positionsnummer_Text: U100
 | H2 Ebene +1 | WI-GKF | 1163Wa 0814759789 | yes | Codetext | m² | Trockenbauarbeiten | Wand | "BS-Beplankung; 2-fach Gipsfaserplatten" | WI-GKF | 0 | A | 3.75 | 1163HWa0813764687 | NEW | no | no | EI 60-A1 - D,s2,d0 +A1 | 0 | no | 0 | no | Codetext | AllplanAttributes - Positionsnummer_Text: U100
 | H2 Ebene +1 | WI-LW 60 | 1163Wa 0814385267 | yes |  | m² | Trockenbauarbeiten | Wand | Innenwand 1-Schalig | WI-LW 60 |  |  | 3.75 | 1163HWa0812434291 | NEW | yes | no | 0 | AllplanAttributes - W_Deckenanschluss: Gleitender Deckenanschluss Fall 01; ash_W_Trockenbau_Qualitäten: 12c; Positionsnummer_Text: U100
 | H2 Ebene +1 | WI-GKF | 1163Wa 0814759823 | yes | Codetext | m² | Trockenbauarbeiten | Wand | "BS-Beplankung; 2-fach Gipsfaserplatten" | WI-GKF | 0 | A | 3.75 | 1163HWa0813764687 | NEW | no | no | EI 60-A1 - D,s2,d0 +A1 | 0 | no | 0 | no | Codetext | AllplanAttributes - Positionsnummer_Text: U100
 | H2 Ebene +1 | WI-GKF | 1163Wa 0814759839 | yes | Codetext | m² | Trockenbauarbeiten | Wand | "BS-Beplankung; 2-fach Gipsfaserplatten" | WI-GKF | 0 | A | 3.75 | 1163HWa0813764687 | NEW | no | no | EI 60-A1 - D,s2,d0 +A1 | 0 | no | 0 | no | Codetext | AllplanAttributes - Positionsnummer_Text: U100
 | H2 Ebene +1 | WI-LB | 1163Wa 0813668626 | yes | Codetext | m² | Trockenbauarbeiten | Wand | Innenwand 1-Schalig | WI-LB | 0 | A | 3.75 | 1163HWa0813668625 | NEW |  | no | 0 | 0 | no | 0 | no | Codetext | AllplanAttributes - W_Deckenanschluss: Gleitender Deckenanschluss Fall 01; ash_W_Trockenbau_Qualitäten: 13; Positionsnummer_Text: U100
 | H2 Ebene +1 | WI-LB | 1163Wa 0814418677 | yes | Codetext | m² | Trockenbauarbeiten | Wand | Innenwand 1-Schalig | WI-LB | 0 | A | 3.75 | 1163HWa0812654445 | NEW | no | no | REI 60-A1 - D,s2-d0 /A1 | 0 | no | 0 | no | Codetext | AllplanAttributes - ash_W_Trockenbau_Qualitäten: 16; Positionsnummer_Text: U100
 | H2 Ebene +1 | WI-HW 60 | 1163Wa 0814418673 | yes | Codetext | m² | Zimmer- und Holzbauarbeiten | Wand | Innenwand 1-Schalig | WI-HW 60 | 0 | A | 3.75 | 1163HWa0812654445 | NEW | yes | no | REI 60-A1 - D,s2-d0 /A1 | 0 | no | 0 | no | Codetext | AllplanAttributes - ash W_laufende Nr. Statik: 3 (W 3.0); Positionsnummer_Text: U100
 | H2 Ebene +1 | WI-LB | 1163Wa 0813903353 | yes | Codetext | m² | Trockenbauarbeiten | Wand | Innenwand 1-Schalig | WI-LB | 0 | A | 3.75 | 1163HWa0813903074 | NEW | no | no | REI 60-A1 - D,s2-d0 /A1 | 0 | no | 0 | no | Codetext | AllplanAttributes - W_Deckenanschluss: Gleitender Deckenanschluss Fall 01; ash_W_Trockenbau_Qualitäten: 12b; Positionsnummer_Text: U100
 | H2 Ebene +1 | WI-HW 60 | 1163Wa 0812447387 | yes | Codetext | m² | Zimmer- und Holzbauarbeiten | Wand | Innenwand 1-Schalig | WI-HW 60 | 0 | A | 3.75 | 1163HWa0812437934 | NEW | yes | no | 0 | 0 | no | 0 | no | Codetext | AllplanAttributes - ash W_laufende Nr. Statik: 7 (W 6.0-1); Positionsnummer_Text: U100
 | H2 Ebene +1 | WI-LB | 1163Wa 0814132265 | yes | Codetext | m² | Trockenbauarbeiten | Wand | Innenwand 1-Schalig | WI-LB | 0 | A | 3.75 | 1113HWa0812553533 | NEW | no | no | REI 60-A1 - D,s2-d0 /A1 | 0 | no | 0 | no | Codetext | AllplanAttributes - ash_W_Trockenbau_Qualitäten: 16; Sicherheitsklasse: -; Positionsnummer_Text: U100
 | H2 Ebene +1 | WI-HW 60 | 1163Wa 0814292080 | yes | Codetext | m² | Zimmer- und Holzbauarbeiten | Wand | Innenwand 1-Schalig | WI-HW 60 | 0 | A | 3.75 | 1163HWa0812474331 | NEW | yes | no | REI 60-A1 - D,s2-d0 +A1 | 0 | no | 0 | no | Codetext | AllplanAttributes - ash W_laufende Nr. Statik: 3 (W 3.0); Positionsnummer_Text: U100
 | H2 Ebene +1 | WI-HW 60 | 1163Wa 0812498502 | yes | Codetext | m² | Zimmer- und Holzbauarbeiten | Wand | Innenwand 1-Schalig | WI-HW 60 | 0 | A | 3.75 | 1163HWa0812498501 | NEW | no | no | 0 | 0 | no | 0 | no | Codetext | AllplanAttributes - Sicherheitsklasse: -; ash W_laufende Nr. Statik: 3 (W 3.0); Positionsnummer_Text: U100
 | H2 Ebene +1 | WI-LB | 1163Wa 0812840020 | yes | Codetext | m² | Trockenbauarbeiten | Wand | Innenwand 1-Schalig | WI-LB | 0 | A | 3.75 | 1163HWa0812840019 | NEW | no | no | REI 60-A1 - D,s2-d0 /A1 | 0 | no |  | no | Codetext | AllplanAttributes - Ortscode_Geschoßbezeichnung: E01; ash_W_Trockenbau_Qualitäten: 9; Positionsnummer_Text: U100
 | H2 Ebene +1 | WI-LB | 1163Wa 0814705949 | yes | Codetext | m² | Trockenbauarbeiten | Wand | Innenwand 1-Schalig | WI-LB | 0 | A | 3.75 | 1163HWa0814107885 | NEW |  | no | 0 | 0 | no | 0 | no | Codetext | AllplanAttributes - W_Deckenanschluss: Gleitender Deckenanschluss Fall 01; ash_W_Trockenbau_Qualitäten: 1b; Positionsnummer_Text: U100
 | H2 Ebene +1 | WI-LB | 1163Wa 0814778097 | yes | Codetext | m² | Trockenbauarbeiten | Wand | Innenwand 1-Schalig | WI-LB | 0 | A | 3.75 | 1163HWa0814107885 | NEW |  | no | 0 | 0 | no | 47 | no | Codetext | AllplanAttributes - W_Deckenanschluss: Gleitender Deckenanschluss Fall 01; ash_W_Trockenbau_Qualitäten: 1b; Positionsnummer_Text: U100
 | H2 Ebene +1 | WI-LB | 1163Wa 0814705898 | yes | Codetext | m² | Trockenbauarbeiten | Wand | Innenwand 1-Schalig | WI-LB | 0 | A | 3.75 | 1163HWa0814107885 | NEW |  | no | 0 | 0 | no | 47 | no | Codetext | AllplanAttributes - W_Deckenanschluss: Gleitender Deckenanschluss Fall 01; ash_W_Trockenbau_Qualitäten: 1b; Positionsnummer_Text: U100
 | H2 Ebene +1 | WI-LB | 1163Wa 0814778123 | yes | Codetext | m² | Trockenbauarbeiten | Wand | Innenwand 1-Schalig | WI-LB | 0 | A | 3.75 | 1163HWa0814107885 | NEW |  | no | 0 | 0 | no | 0 | no | Codetext | AllplanAttributes - W_Deckenanschluss: Gleitender Deckenanschluss Fall 01; ash_W_Trockenbau_Qualitäten: 1b; Positionsnummer_Text: U100
 | H2 Ebene +1 | WI-STB | 1163Wa 0812447364 | yes | Codetext | m² | Zimmer- und Holzbauarbeiten | Wand | Innenwand 1-Schalig | WI-STB | 0 | A | 3.75 | 1163HWa0812429188 | NEW | yes | no | REI 60-A1 - D,s2-d0 /A1 | 0 | no | 0 | no | Codetext | AllplanAttributes - Positionsnummer_Text: U100
 | H2 Ebene +1 | WI-LB | 1163Wa 0812843889 | yes | Codetext | m² | Trockenbauarbeiten | Wand | Innenwand 1-Schalig | WI-LB | 0 | A | 3.75 | 1163HWa0812429188 | NEW | no | no | REI 60-A1 - D,s2-d0 /A1 | 0 | no | 0 | no | Codetext | AllplanAttributes - ash_W_Trockenbau_Qualitäten: 16; Positionsnummer_Text: U100
 | H2 Ebene +1 | WI-STB | 1163Wa 0812447095 | yes | Codetext | m² | Zimmer- und Holzbauarbeiten | Wand | Außenwand 1-Schalig | WI-STB | 0 | A | 3.75 | 1163HWa0812430737 | NEW | yes | no | REI 60-A1 - D,s2-d0 /A1 | 0 | no | 52 | no | Codetext | AllplanAttributes - Positionsnummer_Text: U100
 | H2 Ebene +1 | WI-STB | 1163Wa 0812447104 | yes | Codetext | m² | Zimmer- und Holzbauarbeiten | Wand | Außenwand 1-Schalig | WI-STB | 0 | A | 3.75 | 1163HWa0812430564 | NEW | yes | no | REI 60-A1 - D,s2-d0 /A1 | 0 | no | 0 | no | Codetext | AllplanAttributes - Ortscode_Geschoßbezeichnung: E01; Positionsnummer_Text: U100
 | H2 Ebene +1 | WI-LB | 1163Wa 0812447073 | yes | Codetext | m² | Trockenbauarbeiten | Wand | Innenwand 1-Schalig | WI-LB | 0 | A | 3.75 | 1163HWa0812434671 | NEW |  | no | 0 | 0 | no | 52 | no | Codetext | AllplanAttributes - Ortscode_Geschoßbezeichnung: E01; W_Deckenanschluss: Gleitender Deckenanschluss Fall 01; ash_W_Trockenbau_Qualitäten: 4; Positionsnummer_Text: U100
 | H2 Ebene +1 | WI-HW 60 | 1163Wa 0814777956 | yes | Codetext | m² | Zimmer- und Holzbauarbeiten | Wand | Innenwand 1-Schalig | WI-HW 60 | 0 | A | 3.75 | 1163HWa0812437934 | NEW | yes | no | 0 | 0 | no | 0 | no | Codetext | AllplanAttributes - ash W_laufende Nr. Statik: 7 (W 6.0-1); Positionsnummer_Text: U100
 | H2 Ebene +1 | WI-LB | 1163Wa 0814777957 | yes | Codetext | m² | Trockenbauarbeiten | Wand | Innenwand 1-Schalig | WI-LB | 0 | A | 3.75 | 1113HWa0812553533 | NEW | no | no | REI 60-A1 - D,s2-d0 /A1 | 0 | no | 0 | no | Codetext | AllplanAttributes - ash_W_Trockenbau_Qualitäten: 20; Sicherheitsklasse: -; Positionsnummer_Text: U100
 | H2 Ebene +1 | WI-LB | 1163Wa 0812447098 | yes | Codetext | m² | Trockenbauarbeiten | Wand | Innenwand 1-Schalig | WI-LB | 0 | A | 3.75 | 1163HWa0812434685 | NEW |  | no | 0 | 0 | no | 52 | no | Codetext | AllplanAttributes - Ortscode_Geschoßbezeichnung: E01; W_Deckenanschluss: Gleitender Deckenanschluss Fall 01; ash_W_Trockenbau_Qualitäten: 4; Positionsnummer_Text: U100
 | H2 Ebene +1 | WI-HW 60 | 1163Wa 0814614142 | yes | Codetext | m² | Zimmer- und Holzbauarbeiten | Wand | Innenwand 1-Schalig | WI-HW 60 | 0 | A | 3.75 | 1163HWa0812439461 | NEW | yes | no | REI 60-A1 - D,s2-d0 +A1 | 0 | no | 47 | no | Codetext | AllplanAttributes - ash W_laufende Nr. Statik: 1 (W 1.0/ 1.1/ 1.2); Positionsnummer_Text: U100
 | H2 Ebene +1 | WI-LB | 1163Wa 0812754801 | yes | Codetext | m² | Trockenbauarbeiten | Wand | Innenwand 1-Schalig | WI-LB | 0 | A | 3.75 | 1163HWa0812754799 | NEW | no | no | 0 | 0 | no | 47 | no | Codetext | AllplanAttributes - ash_W_Trockenbau_Qualitäten: 7; Sicherheitsklasse: -; Positionsnummer_Text: U100
 | H2 Ebene +1 | WI-HW 60 | 1163Wa 0813788239 | yes | Codetext | m² | Zimmer- und Holzbauarbeiten | Wand | Innenwand 1-Schalig | WI-HW 60 | 0 | A | 3.75 | 1163HWa0812754799 | NEW | no | no | 0 | 0 | no | 47 | no | Codetext | AllplanAttributes - Sicherheitsklasse: -; ash W_laufende Nr. Statik: 3 (W 3.0); Positionsnummer_Text: U100
 | H2 Ebene +1 | WI-LB | 1163Wa 0812438677 | yes | Codetext | m² | Trockenbauarbeiten | Wand | Innenwand 1-Schalig | WI-LB | 0 | A | 3.75 | 1163HWa0812438496 | NEW | no | no | 0 | 0 | no | 52 | no | Codetext | AllplanAttributes - ash_W_Trockenbau_Qualitäten: 7; Sicherheitsklasse: -; Positionsnummer_Text: U100
 | H2 Ebene +1 | WI-HW 60 | 1163Wa 0813788354 | yes | Codetext | m² | Zimmer- und Holzbauarbeiten | Wand | Innenwand 1-Schalig | WI-HW 60 | 0 | A | 3.75 | 1163HWa0812438496 | NEW | no | no | 0 | 0 | no | 52 | no | Codetext | AllplanAttributes - Sicherheitsklasse: -; ash W_laufende Nr. Statik: 3 (W 3.0); Positionsnummer_Text: U100
 | H2 Ebene +1 | WI-STB | 1163Wa 0812542271 | yes | Codetext | m² | Zimmer- und Holzbauarbeiten | Wand | Außenwand 1-Schalig | WI-STB | 0 | A | 3.75 | 1163HWa0812542250 | NEW | yes | no | REI 60-A1 - D,s2-d0 /A1 | 0 | no | 0 | no | Codetext | AllplanAttributes - Ortscode_Geschoßbezeichnung: E01; Positionsnummer_Text: U100
 | H2 Ebene +1 | WI-HW 60 | 1163Wa 0812446933 | yes |  | m² | Zimmer- und Holzbauarbeiten | Wand | Innenwand 1-Schalig | WI-HW 60 |  |  | 3.75 | 1163HWa0812446815 | NEW | yes | no | REI-M 60-D,s2,d0 + A1 |  |  | 47 | AllplanAttributes - ash W_laufende Nr. Statik: 7 (W 6.0-1); Positionsnummer_Text: U100
 | H2 Ebene +1 | WI-HW 60 | 1163Wa 0814779081 | yes |  | m² | Zimmer- und Holzbauarbeiten | Wand | Innenwand 1-Schalig | WI-HW 60 |  |  | 3.75 | 1163HWa0812446815 | NEW | yes | no | REI-M 60-D,s2,d0 + A1 | AllplanAttributes - ash W_laufende Nr. Statik: 7 (W 6.0-1); Positionsnummer_Text: U100
 | H2 Ebene +1 | WI-HW 60 | 1163Wa 0812551376 | yes | Codetext | m² | Zimmer- und Holzbauarbeiten | Wand | Innenwand 1-Schalig | WI-HW 60 | 0 | A | 3.75 | 1163HWa0812551333 | NEW | no | no | REI 30-A1 - D,s2-d0 +A1 | 0 | no | 0 | no | Codetext | AllplanAttributes - ash W_laufende Nr. Statik: 3 (W 3.0); Positionsnummer_Text: U100
 | H2 Ebene +1 | WI-LB | 1163Wa 0813787831 | yes | Codetext | m² | Trockenbauarbeiten | Wand | Innenwand 1-Schalig | WI-LB | 0 | A | 3.75 | 1163HWa0812551333 | NEW | no | no | REI 30-A1 - D,s2-d0 +A1 | 0 | no | 0 | no | Codetext | AllplanAttributes - ash_W_Trockenbau_Qualitäten: 6; Positionsnummer_Text: U100
 | H2 Ebene +1 | WI-HW 60 | 1163Wa 0812553865 | yes |  | m² | Zimmer- und Holzbauarbeiten | Wand | Innenwand 1-Schalig | WI-HW 60 |  |  | 3.75 | 1163HWa0812437912 | NEW | yes | no | REI-M 60-D,s2,d0 + A1 |  |  | 42 | AllplanAttributes - ash W_laufende Nr. Statik: 7 (W 6.0-1); Positionsnummer_Text: U100
 | H2 Ebene +1 | WI-LB | 1163Wa 0814100809 | yes | Codetext | m² | Trockenbauarbeiten | Wand | Innenwand 1-Schalig | WI-LB | 0 | A | 3.75 | 1113HWa0812553533 | NEW | no | no | REI 60-A1 - D,s2-d0 /A1 | 0 | no | 42 | no | Codetext | AllplanAttributes - ash_W_Trockenbau_Qualitäten: 16; Sicherheitsklasse: -; Positionsnummer_Text: U100
 | H2 Ebene +1 | WI-LB | 1163Wa 0812438684 | yes | Codetext | m² | Trockenbauarbeiten | Wand | Innenwand 1-Schalig | WI-LB | 0 | A | 3.75 | 1163HWa0812438171 | NEW | no | no | 0 | 0 | no | 0 | no | Codetext | AllplanAttributes - W_Deckenanschluss: Gleitender Deckenanschluss Fall 01; ash_W_Trockenbau_Qualitäten: 12b; Positionsnummer_Text: U100
 | H2 Ebene +1 | WI-LB | 1163Wa 0812446151 | yes | Codetext | m² | Trockenbauarbeiten | Wand | Innenwand 1-Schalig | WI-LB | 0 | A | 3.75 | 1163HWa0812434274 | NEW | no | no | 0 | 0 | no | 0 | no | Codetext | AllplanAttributes - W_Deckenanschluss: Gleitender Deckenanschluss Fall 01; ash_W_Trockenbau_Qualitäten: 12b; Positionsnummer_Text: U100
 | H2 Ebene +1 | WI-LB | 1163Wa 0814786922 | yes | Codetext | m² | Trockenbauarbeiten | Wand | Außenwand 2-Schalig | WI-LB | 0 | A | 3.75 | 1163HWa0812447232 | NEW | no | no | 0 | 0 | no |  | no | Codetext | AllplanAttributes - Ortscode_Geschoßbezeichnung: E00; ash_W_Trockenbau_Qualitäten: 9; Sicherheitsklasse: -; Positionsnummer_Text: U100
 | H2 Ebene +1 | WI-LB | 1163Wa 0812447355 | yes | Codetext | m² | Trockenbauarbeiten | Wand | Innenwand 1-Schalig | WI-LB | 0 | A | 3.75 | 1163HWa0812447234 | NEW | no | no | REI 60-A1 - D,s2-d0 /A1 | 0 | no |  | no | Codetext | AllplanAttributes - ash_W_Trockenbau_Qualitäten: 6; Positionsnummer_Text: U100
 | H2 Ebene +1 | WI-STB | 1163Wa 0814078116 | yes | Codetext | m² | Zimmer- und Holzbauarbeiten | Wand | Innenwand 1-Schalig | WI-STB | 0 | A | 3.75 | 1163HWa0812447234 | NEW | yes | no | REI 60-A1 - D,s2-d0 /A1 | 0 | no | 0 | no | Codetext | AllplanAttributes - Positionsnummer_Text: U100
 | H2 Ebene +1 | WI-LB | 1163Wa 0814787072 | yes | Codetext | m² | Trockenbauarbeiten | Wand | Innenwand 1-Schalig | WI-LB | 0 | A | 3.75 | 1163HWa0812447234 | NEW | no | no | REI 60-A1 - D,s2-d0 /A1 | 0 | no |  | no | Codetext | AllplanAttributes - ash_W_Trockenbau_Qualitäten: 6; Positionsnummer_Text: U100
 | H2 Ebene +1 | WI-STB | 1163Wa 0814787073 | yes | Codetext | m² | Zimmer- und Holzbauarbeiten | Wand | Innenwand 1-Schalig | WI-STB | 0 | A | 3.75 | 1163HWa0812447234 | NEW | yes | no | REI 60-A1 - D,s2-d0 /A1 | 0 | no | 0 | no | Codetext | AllplanAttributes - Positionsnummer_Text: U100
 | H2 Ebene +1 | WI-LB | 1163Wa 0814787146 | yes | Codetext | m² | Trockenbauarbeiten | Wand | Innenwand 1-Schalig | WI-LB | 0 | A | 3.75 | 1163HWa0812429188 | NEW | no | no | REI 60-A1 - D,s2-d0 /A1 | 0 | no | 0 | no | Codetext | AllplanAttributes - ash_W_Trockenbau_Qualitäten: 6; Positionsnummer_Text: U100
 | H2 Ebene +1 | WI-LB | 1163Wa 0812531640 | yes | Codetext | m² | Trockenbauarbeiten | Wand | Innenwand 1-Schalig | WI-LB | 0 | A | 3.75 | 1163HWa0812531522 | NEW | yes | no | REI 60-A1 - D,s2-d0 +A1 | 0 | no | 0 | no | Codetext | AllplanAttributes - W_Deckenanschluss: Gleitender Deckenanschluss Fall 01; ash_W_Trockenbau_Qualitäten: 12b; Positionsnummer_Text: U100
 | H2 Ebene +1 | WI-LB | 1163Wa 0812440009 | yes |  | m² | Trockenbauarbeiten | Wand | Innenwand 1-Schalig | WI-LB |  |  | 3.75 | 1163HWa0812437927 | NEW | yes | no | REI-M 60-D,s2,d0 + A1 |  |  | 0 | AllplanAttributes - ash_W_Trockenbau_Qualitäten: 12a; Positionsnummer_Text: U100
 | H2 Ebene +1 | WI-LB | 1163Wa 0813652957 | yes | Codetext | m² | Trockenbauarbeiten | Wand | Innenwand 1-Schalig | WI-LB | 0 | A | 3.75 | 1163HWa0813652933 | NEW | no | no | 0 | 0 | no | 0 | no | Codetext | AllplanAttributes - W_Deckenanschluss: Gleitender Deckenanschluss Fall 01; Positionsnummer_Text: U100
 | H2 Ebene +1 | WI-STB | 1163Wa 0812840575 | yes | Codetext | m² | Zimmer- und Holzbauarbeiten | Wand | Innenwand 1-Schalig | WI-STB | 0 | A | 3.75 | 1163HWa0812840573 | NEW | yes | no | REI-M 60-A1 | 0 | no | 0 | no | Codetext | AllplanAttributes - Ortscode_Geschoßbezeichnung: E01; Positionsnummer_Text: U100
 | H2 Ebene +1 | WI-STB | 1163Wa 0812443669 | yes | Codetext | m² | Zimmer- und Holzbauarbeiten | Wand | Innenwand 1-Schalig | WI-STB | 0 | A | 3.75 | 1163HWa0812430718 | NEW | yes | no | REI-M 60-A1 | 0 | no | 0 | no | Codetext | AllplanAttributes - Ortscode_Geschoßbezeichnung: E01; Positionsnummer_Text: U100
 | H2 Ebene +1 | WI-LB | 1163Wa 0812840793 | yes | Codetext | m² | Trockenbauarbeiten | Wand | Innenwand 1-Schalig | WI-LB | 0 | A | 3.75 | 1163HWa0812840791 | NEW | no | no | REI 60-A1 - D,s2-d0 /A1 | 0 | no | 0 | no | Codetext | AllplanAttributes - Ortscode_Geschoßbezeichnung: E01; ash_W_Trockenbau_Qualitäten: 9; Positionsnummer_Text: U100
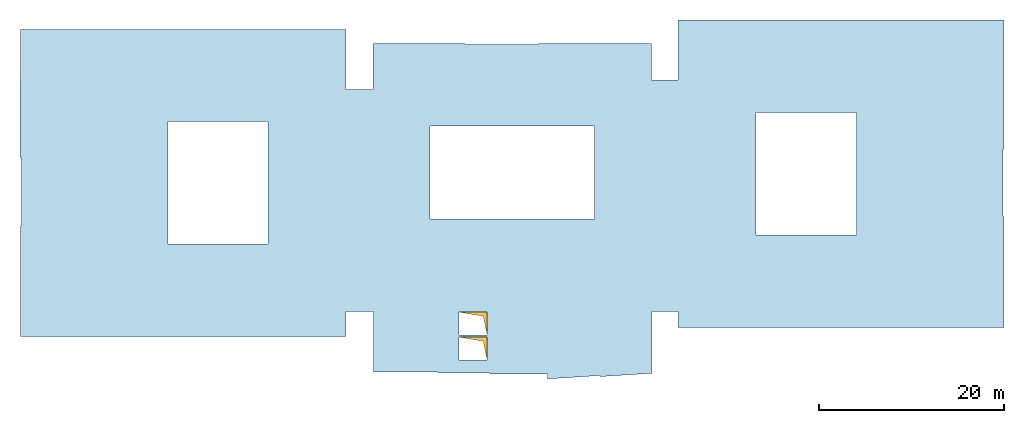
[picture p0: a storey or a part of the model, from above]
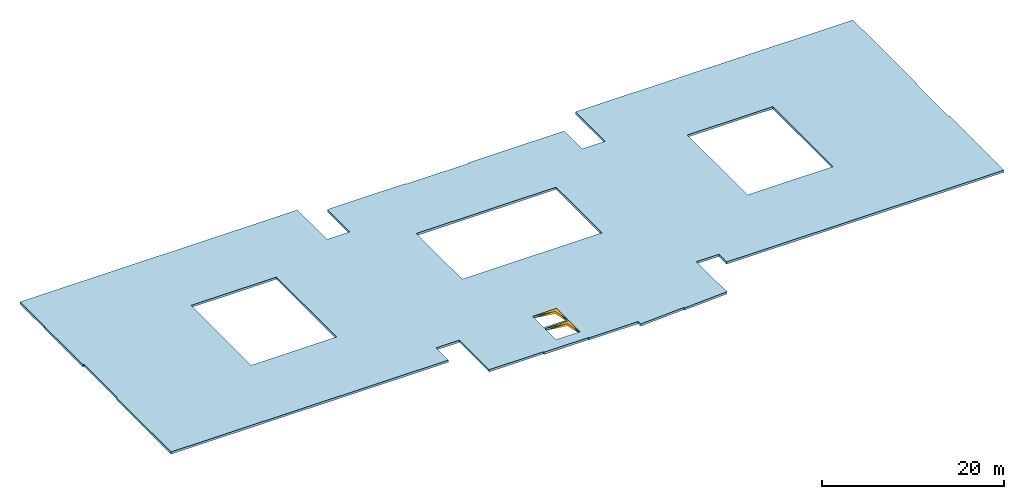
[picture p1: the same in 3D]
Properties of the parts of a building model (IFC4), part 69 of 80

# IfcWall (6826)
Name | In | Material | Allright_Bauteil_ID | 2D Interaktion | Codetext | Abrechnungsart | Gewerk | Objektname | Bezeichnung | AllplanAttributes, Material | Typ = SurfaceSpreadOfFlame | Brandschutzklasse | OKFF | P_ID | Status | LoadBearing | IsExternal | FireRating | ThermalTransmittance (W/K/m2) | Combustible | AcousticRating | Compartmentation | Reference
 | H2 Ebene +1 | WI-STB | 1163Wa 0812840813 | yes | Codetext | m² | Zimmer- und Holzbauarbeiten | Wand | Innenwand 1-Schalig | WI-STB | 0 | A | 3.75 | 1163HWa0812840791 | NEW | yes | no | REI-M 60-A1 | 0 | no | 0 | no | Codetext | AllplanAttributes - Ortscode_Geschoßbezeichnung: E01; Positionsnummer_Text: U100
 | H2 Ebene +1 | WI-STB | 1163Wa 0812437244 | yes | Codetext | m² | Zimmer- und Holzbauarbeiten | Wand | Außenwand 1-Schalig | WI-STB | 0 | A | 3.75 | 1163HWa0812428689 | NEW | yes | no | REI-M 60-A1 | 0 | no | 0 | no | Codetext | AllplanAttributes - Ortscode_Geschoßbezeichnung: E01; Positionsnummer_Text: U100
 | H2 Ebene +1 | WI-LB | 1163Wa 0812846194 | yes | Codetext | m² | Trockenbauarbeiten | Wand | Außenwand 1-Schalig | WI-LB | 0 | A | 3.75 | 1163HWa0812846192 | NEW | no | no | REI 60-A1 - D,s2-d0 /A1 | 0 | no | 0 | no | Codetext | AllplanAttributes - Ortscode_Geschoßbezeichnung: E01; ash_W_Trockenbau_Qualitäten: 9; Positionsnummer_Text: U100
 | H2 Ebene +1 | WI-STB | 1163Wa 0812846226 | yes | Codetext | m² | Zimmer- und Holzbauarbeiten | Wand | Außenwand 1-Schalig | WI-STB | 0 | A | 3.75 | 1163HWa0812846192 | NEW | yes | no | REI-M 60-A1 | 0 | no | 0 | no | Codetext | AllplanAttributes - Ortscode_Geschoßbezeichnung: E01; Positionsnummer_Text: U100
 | H2 Ebene +1 | WI-STB | 1163Wa 0812437765 | yes | Codetext | m² | Zimmer- und Holzbauarbeiten | Wand | Außenwand 1-Schalig | WI-STB | 0 | A | 3.75 | 1163HWa0812428686 | NEW | yes | no | REI-M 60-A1 | 0 | no | 0 | no | Codetext | AllplanAttributes - Ortscode_Geschoßbezeichnung: E01; Positionsnummer_Text: U100
 | H2 Ebene +1 | WI-STB | 1163Wa 0812438050 | yes |  | m² | Zimmer- und Holzbauarbeiten | Wand | Innenwand 1-Schalig | WI-STB |  |  | 3.75 | 1163HWa0812435122 | NEW | yes | no | REI-M 60-A1 | AllplanAttributes - Ortscode_Geschoßbezeichnung: E01; Positionsnummer_Text: U100
 | H2 Ebene +1 | WI-STB | 1163Wa 0812447417 | yes |  | m² | Zimmer- und Holzbauarbeiten | Wand | Innenwand 1-Schalig | WI-STB |  |  | 3.75 | 1163HWa0812437907 | NEW | yes | no | REI-M 60-A1 | AllplanAttributes - Ortscode_Geschoßbezeichnung: E01; Positionsnummer_Text: U100
 | H2 Ebene +1 | WI-LB | 1163Wa 0812437888 | yes | Codetext | m² | Trockenbauarbeiten | Wand | Innenwand 1-Schalig | WI-LB | 0 | A | 3.75 | 1163HWa0812434405 | NEW | no | no | REI 60-A1 - D,s2-d0 /A1 | 0 | no | 0 | no | Codetext | AllplanAttributes - ash_W_Trockenbau_Qualitäten: 9; Positionsnummer_Text: U100
 | H2 Ebene +1 | WI-STB | 1163Wa 0812845014 | yes | Codetext | m² | Zimmer- und Holzbauarbeiten | Wand | Innenwand 1-Schalig | WI-STB | 0 | A | 3.75 | 1163HWa0812434405 | NEW | yes | no | REI-M 60-A1 | 0 | no | 42 | no | Codetext | AllplanAttributes - Positionsnummer_Text: U100
 | H2 Ebene +1 | WI-STB | 1163Wa 0812437655 | yes | Codetext | m² | Zimmer- und Holzbauarbeiten | Wand | Außenwand 1-Schalig | WI-STB | 0 | A | 3.75 | 1163HWa0812428688 | NEW | yes | no | REI-M 60-A1 | 0 | no | 0 | no | Codetext | AllplanAttributes - Ortscode_Geschoßbezeichnung: E01; Positionsnummer_Text: U100
 | H2 Ebene +1 | WI-LB | 1163Wa 0812847543 | yes | Codetext | m² | Trockenbauarbeiten | Wand | Außenwand 1-Schalig | WI-LB | 0 | A | 3.75 | 1163HWa0812428688 | NEW | no | no | REI 60-A1 - D,s2-d0 /A1 | 0 | no | 0 | no | Codetext | AllplanAttributes - Ortscode_Geschoßbezeichnung: E01; ash_W_Trockenbau_Qualitäten: 9; Positionsnummer_Text: U100
 | H2 Ebene +1 | WA-STB | 1163Wa 0812437306 | yes | Codetext | m² | Zimmer- und Holzbauarbeiten | Wand | Außenwand 1-Schalig | WA-STB | 0 | A | 3.75 | 1163HWa0812425596 | NEW | yes | no | REI-M 60-A1 | 0 | no | 0 | no | Codetext | AllplanAttributes - Ortscode_Geschoßbezeichnung: E01; Positionsnummer_Text: U100
 | H2 Ebene +1 | WI-STB | 1163Wa 0812444131 | yes | Codetext | m² | Zimmer- und Holzbauarbeiten | Wand | Innenwand 1-Schalig | WI-STB | 0 | A | 3.75 | 1163HWa0812428697 | NEW | yes | no | REI-M 60-A1 | 0 | no | 0 | no | Codetext | AllplanAttributes - Ortscode_Geschoßbezeichnung: E01; Positionsnummer_Text: U100
 | H2 Ebene +1 | WI-LB | 1163Wa 0812840160 | yes | Codetext | m² | Trockenbauarbeiten | Wand | Innenwand 1-Schalig | WI-LB | 0 | A | 3.75 | 1163HWa0812428697 | NEW | no | no | REI 60-A1 - D,s2-d0 /A1 | 0 | no | 0 | no | Codetext | AllplanAttributes - Ortscode_Geschoßbezeichnung: E01; ash_W_Trockenbau_Qualitäten: 9; Positionsnummer_Text: U100
 | H2 Ebene +1 | WI-STB | 1163Wa 0814418471 | yes | Codetext | m² | Zimmer- und Holzbauarbeiten | Wand | Innenwand 1-Schalig | WI-STB | 0 | A | 3.75 | 1163HWa0812428685 | NEW | yes | no | REI-M 60-A1 | 0 | no | 0 | no | Codetext | AllplanAttributes - Ortscode_Geschoßbezeichnung: E01; Positionsnummer_Text: U100
 | H2 Ebene +1 | WI-STB | 1163Wa 0814418476 | yes | Codetext | m² | Zimmer- und Holzbauarbeiten | Wand | Außenwand 1-Schalig | WI-STB | 0 | A | 3.75 | 1163HWa0812434407 | NEW | yes | no | REI-M 60-A1 | 0 | no | 0 | no | Codetext | AllplanAttributes - Ortscode_Geschoßbezeichnung: E01; Positionsnummer_Text: U100
 | H2 Ebene +1 | WI-LB | 1163Wa 0812443671 | yes | Codetext | m² | Trockenbauarbeiten | Wand | Innenwand 1-Schalig | WI-LB | 0 | A | 3.75 | 1163HWa0812428695 | NEW | no | no | REI 60-A1 - D,s2-d0 /A1 | 0 | no | 0 | no | Codetext | AllplanAttributes - Ortscode_Geschoßbezeichnung: E01; ash_W_Trockenbau_Qualitäten: 9; Positionsnummer_Text: U100
 | H2 Ebene +1 | WI-STB | 1163Wa 0812840229 | yes | Codetext | m² | Zimmer- und Holzbauarbeiten | Wand | Innenwand 1-Schalig | WI-STB | 0 | A | 3.75 | 1163HWa0812428695 | NEW | yes | no | REI-M 60-A1 | 0 | no | 0 | no | Codetext | AllplanAttributes - Ortscode_Geschoßbezeichnung: E01; ash D_Detailverweis: Lösch; ash D_Plannummer: 1682; Positionsnummer_Text: U100
 | H2 Ebene +1 | WI-STB | 1163Wa 0812437352 | yes | Codetext | m² | Zimmer- und Holzbauarbeiten | Wand | Außenwand 1-Schalig | WI-STB | 0 | A | 3.75 | 1163HWa0812434408 | NEW | yes | no | REI-M 60-A1 | 0 | no | 0 | no | Codetext | AllplanAttributes - Text1: Feinputz an Wandseite zum Speisewagenraum; Positionsnummer_Text: U100
 | H2 Ebene +1 | WI-LB | 1163Wa 0814594136 | yes | Codetext | m² | Trockenbauarbeiten | Wand | Außenwand 1-Schalig | WI-LB | 0 | A | 3.75 | 1163HWa0812840791 | NEW | no | no | REI 60-A1 - D,s2-d0 /A1 | 0 | no | 0 | no | Codetext | AllplanAttributes - ash_W_Trockenbau_Qualitäten: 9; Text1: Feinputz an Wandseite zum Speisewagenraum; Positionsnummer_Text: U100
 | H2 Ebene +1 | WI-STB | 1163Wa 0812437354 | yes | Codetext | m² | Zimmer- und Holzbauarbeiten | Wand | Außenwand 1-Schalig | WI-STB | 0 | A | 3.75 | 1163HWa0812428692 | NEW | yes | no | REI-M 60-A1 | 0 | no | 0 | no | Codetext | AllplanAttributes - Text1: Feinputz an Wandseite zum Speisenwagenraum; Positionsnummer_Text: U100
 | H2 Ebene +1 | WI-LB | 1163Wa 0814594206 | yes | Codetext | m² | Trockenbauarbeiten | Wand | Außenwand 1-Schalig | WI-LB | 0 | A | 3.75 | 1163HWa0812840791 | NEW | no | no | REI 60-A1 - D,s2-d0 /A1 | 0 | no | 0 | no | Codetext | AllplanAttributes - ash_W_Trockenbau_Qualitäten: 9; Text1: Feinputz an Wandseite zum Speisenwagenraum; Positionsnummer_Text: U100
 | H2 Ebene +1 | WI-STB | 1163Wa 0814594518 | yes | Codetext | m² | Zimmer- und Holzbauarbeiten | Wand | Außenwand 1-Schalig | WI-STB | 0 | A | 3.75 | 1163HWa0812434407 | NEW | yes | no | REI-M 60-A1 | 0 | no | 0 | no | Codetext | AllplanAttributes - Positionsnummer_Text: U100
 | H2 Ebene +1 | WI-STB | 1163Wa 0812443688 | yes | Codetext | m² | Zimmer- und Holzbauarbeiten | Wand | Innenwand 1-Schalig | WI-STB | 0 | A | 3.75 | 1163HWa0812428694 | NEW | yes | no | REI-M 60-A1 | 0 | no | 0 | no | Codetext | AllplanAttributes - Ortscode_Geschoßbezeichnung: E01; Positionsnummer_Text: U100
 | H2 Ebene +1 | WI-LB | 1163Wa 0812840607 | yes | Codetext | m² | Trockenbauarbeiten | Wand | Innenwand 1-Schalig | WI-LB | 0 | A | 3.75 | 1163HWa0812428694 | NEW | no | no | REI 60-A1 - D,s2-d0 /A1 | 0 | no | 0 | no | Codetext | AllplanAttributes - Ortscode_Geschoßbezeichnung: E01; ash_W_Trockenbau_Qualitäten: 9; Positionsnummer_Text: U100
 | H2 Ebene 0 | WI-LB | 1105Wa 0811390135 |  |  | m² | Trockenbauarbeiten | Wand | Innenwand 1-Schalig | WI-LB |  |  |  |  |  |  |  | 0 | AllplanAttributes - Sicherheitsklasse: -
 | H2 Ebene 0 | WA-STB | 1105Wa 0000019884 |  |  | m² | Zimmer- und Holzbauarbeiten | Wand | Außenwand 2-Schalig | WA-STB |  |  | 0 |  |  |  |  | 0 | AllplanAttributes - Ortscode_Geschoßbezeichnung: E00; ash D_Detailverweis: X7; ash D_Plannummer: D1861; Sicherheitsklasse: -
 | H2 Ebene 0 | WA-DL | 1105Wa 0000019885 |  |  | m³ | Zimmer- und Holzbauarbeiten | Wand | Außenwand 2-Schalig | WA-DL |  |  | 0 |  |  |  |  | 0 | AllplanAttributes - Ortscode_Geschoßbezeichnung: E00; ash D_Detailverweis: X7; ash D_Plannummer: D1861; Sicherheitsklasse: -
 | H2 Ebene 0 | WA-LB | 1105Wa 0811567723 |  |  | m² | Trockenbauarbeiten | Wand | Außenwand 7-Schalig | WA-LB |  |  | 0 |  |  |  |  | 0 | AllplanAttributes - Ortscode_Geschoßbezeichnung: E00; Sicherheitsklasse: -
 | H2 Ebene 0 | WA-LB | 1105Wa 0811564948 |  |  | m² | Trockenbauarbeiten | Wand | Außenwand 7-Schalig | WA-LB |  |  | 0 |  |  |  |  | 0 | AllplanAttributes - Ortscode_Geschoßbezeichnung: E00; Sicherheitsklasse: -
 | H2 Ebene 0 | WA-LB | 1105Wa 0811649298 |  |  | m² | Trockenbauarbeiten | Wand | Außenwand 7-Schalig | WA-LB |  |  | 0 |  |  |  |  | 0 | AllplanAttributes - Ortscode_Geschoßbezeichnung: E00; Sicherheitsklasse: -
 | H2 Ebene 0 | WA-LB | 1105Wa 0000062684 |  |  | m² | Trockenbauarbeiten | Wand | Außenwand 7-Schalig | WA-LB |  |  | 0 |  |  |  |  | 0 | AllplanAttributes - Ortscode_Geschoßbezeichnung: E00; Sicherheitsklasse: -
 | H2 Ebene 0 | WA-HD | 1105Wa 0000062683 |  |  | m³ | Zimmer- und Holzbauarbeiten | Wand | Außenwand 7-Schalig | WA-HD |  |  | 0 |  |  |  |  | 0 | AllplanAttributes - Ortscode_Geschoßbezeichnung: E00; Sicherheitsklasse: -
 | H2 Ebene 0 | WA-DL | 1105Wa 0000062685 |  |  | m³ | Zimmer- und Holzbauarbeiten | Wand | Außenwand 7-Schalig | WA-DL |  |  | 0 |  |  |  |  | 0 | AllplanAttributes - Ortscode_Geschoßbezeichnung: E00; Sicherheitsklasse: -
 | H2 Ebene 0 | WA-TP | 1105Wa 0000062686 |  |  | m² | Zimmer- und Holzbauarbeiten | Wand | Außenwand 7-Schalig | WA-TP |  |  | 0 |  |  |  |  | 0 | AllplanAttributes - Ortscode_Geschoßbezeichnung: E00; Sicherheitsklasse: -
 | H2 Ebene 0 | WA-KL | 1105Wa 0000062687 |  |  | m² | Zimmer- und Holzbauarbeiten | Wand | Außenwand 7-Schalig | WA-KL |  |  | 0 |  |  |  |  | 0 | AllplanAttributes - Ortscode_Geschoßbezeichnung: E00; Sicherheitsklasse: -
 | H2 Ebene 0 | WA-TL | 1105Wa 0000062688 |  |  | m² | Zimmer- und Holzbauarbeiten | Wand | Außenwand 7-Schalig | WA-TL |  |  | 0 |  |  |  |  | 0 | AllplanAttributes - Ortscode_Geschoßbezeichnung: E00; Sicherheitsklasse: -
 | H2 Ebene 0 | WA-HS | 1105Wa 0811633379 |  |  | m² | Zimmer- und Holzbauarbeiten | Wand | Außenwand 7-Schalig | WA-HS |  |  | 0 |  |  |  |  | 0 | AllplanAttributes - Ortscode_Geschoßbezeichnung: E00; Sicherheitsklasse: -
 | H2 Ebene 0 | WA-LB | 1105Wa 0811650637 |  |  | m² | Trockenbauarbeiten | Wand | Außenwand 7-Schalig | WA-LB |  |  | 0 |  |  |  |  | 0 | AllplanAttributes - Ortscode_Geschoßbezeichnung: E00; Sicherheitsklasse: -
 | H2 Ebene 0 | WA-HD | 1105Wa 0811650638 |  |  | m³ | Zimmer- und Holzbauarbeiten | Wand | Außenwand 7-Schalig | WA-HD |  |  | 0 |  |  |  |  | 0 | AllplanAttributes - Ortscode_Geschoßbezeichnung: E00; Sicherheitsklasse: -
 | H2 Ebene 0 | WA-DL | 1105Wa 0811650633 |  |  | m³ | Zimmer- und Holzbauarbeiten | Wand | Außenwand 7-Schalig | WA-DL |  |  | 0 |  |  |  |  | 0 | AllplanAttributes - Ortscode_Geschoßbezeichnung: E00; Sicherheitsklasse: -
 | H2 Ebene 0 | WA-TP | 1105Wa 0811650634 |  |  | m² | Zimmer- und Holzbauarbeiten | Wand | Außenwand 7-Schalig | WA-TP |  |  | 0 |  |  |  |  | 0 | AllplanAttributes - Ortscode_Geschoßbezeichnung: E00; Sicherheitsklasse: -
 | H2 Ebene 0 | WA-KL | 1105Wa 0811650636 |  |  | m² | Zimmer- und Holzbauarbeiten | Wand | Außenwand 7-Schalig | WA-KL |  |  | 0 |  |  |  |  | 0 | AllplanAttributes - Ortscode_Geschoßbezeichnung: E00; Sicherheitsklasse: -
 | H2 Ebene 0 | WA-TL | 1105Wa 0811650635 |  |  | m² | Zimmer- und Holzbauarbeiten | Wand | Außenwand 7-Schalig | WA-TL |  |  | 0 |  |  |  |  | 0 | AllplanAttributes - Ortscode_Geschoßbezeichnung: E00; Sicherheitsklasse: -
 | H2 Ebene 0 | WA-HS | 1105Wa 0811650632 |  |  | m² | Zimmer- und Holzbauarbeiten | Wand | Außenwand 7-Schalig | WA-HS |  |  | 0 |  |  |  |  | 0 | AllplanAttributes - Ortscode_Geschoßbezeichnung: E00; Sicherheitsklasse: -
 | H2 Ebene 0 | WA-LB | 1105Wa 0000002907 |  |  | m² | Trockenbauarbeiten | Wand | Außenwand 7-Schalig | WA-LB |  |  | 0 |  |  |  |  | 0 | AllplanAttributes - Ortscode_Geschoßbezeichnung: E00; Sicherheitsklasse: -
 | H2 Ebene 0 | WA-DL | 1105Wa 0000002903 |  |  | m³ | Zimmer- und Holzbauarbeiten | Wand | Außenwand 7-Schalig | WA-DL |  |  | 0 |  |  |  |  | 0 | AllplanAttributes - Ortscode_Geschoßbezeichnung: E00; Sicherheitsklasse: -
 | H2 Ebene 0 | WA-DL | 1105Wa 0000002899 |  |  | m³ | Zimmer- und Holzbauarbeiten | Wand | Außenwand 7-Schalig | WA-DL |  |  | 0 |  |  |  |  | 0 | AllplanAttributes - Ortscode_Geschoßbezeichnung: E00; Sicherheitsklasse: -
 | H2 Ebene 0 | WA-TP | 1105Wa 0000002895 |  |  | m² | Zimmer- und Holzbauarbeiten | Wand | Außenwand 7-Schalig | WA-TP |  |  | 0 |  |  |  |  | 0 | AllplanAttributes - Ortscode_Geschoßbezeichnung: E00; Sicherheitsklasse: -
 | H2 Ebene 0 | WA-KL | 1105Wa 0000002891 |  |  | m² | Zimmer- und Holzbauarbeiten | Wand | Außenwand 7-Schalig | WA-KL |  |  | 0 |  |  |  |  | 0 | AllplanAttributes - Ortscode_Geschoßbezeichnung: E00; Sicherheitsklasse: -
 | H2 Ebene 0 | WA-TL | 1105Wa 0000002887 |  |  | m² | Zimmer- und Holzbauarbeiten | Wand | Außenwand 7-Schalig | WA-TL |  |  | 0 |  |  |  |  | 0 | AllplanAttributes - Ortscode_Geschoßbezeichnung: E00; Sicherheitsklasse: -
 | H2 Ebene 0 | WA-HS | 1105Wa 0000002883 |  |  | m² | Zimmer- und Holzbauarbeiten | Wand | Außenwand 7-Schalig | WA-HS |  |  | 0 |  |  |  |  | 0 | AllplanAttributes - Ortscode_Geschoßbezeichnung: E00; Sicherheitsklasse: -
 | H2 Ebene 0 | WA-LB | 1105Wa 0000000388 |  |  | m² | Trockenbauarbeiten | Wand | Außenwand 7-Schalig | WA-LB |  |  | 0 |  |  |  |  | 0 | AllplanAttributes - Ortscode_Geschoßbezeichnung: E00; Sicherheitsklasse: -
 | H2 Ebene 0 | WA-HD | 1105Wa 0000000384 |  |  | m³ | Zimmer- und Holzbauarbeiten | Wand | Außenwand 7-Schalig | WA-HD |  |  | 0 |  |  |  |  | 0 | AllplanAttributes - Ortscode_Geschoßbezeichnung: E00; Sicherheitsklasse: -
 | H2 Ebene 0 | WA-DL | 1105Wa 0000000364 |  |  | m³ | Zimmer- und Holzbauarbeiten | Wand | Außenwand 7-Schalig | WA-DL |  |  | 0 |  |  |  |  | 0 | AllplanAttributes - Ortscode_Geschoßbezeichnung: E00; Sicherheitsklasse: -
 | H2 Ebene 0 | WA-TP | 1105Wa 0000000368 |  |  | m² | Zimmer- und Holzbauarbeiten | Wand | Außenwand 7-Schalig | WA-TP |  |  | 0 |  |  |  |  | 0 | AllplanAttributes - Ortscode_Geschoßbezeichnung: E00; Sicherheitsklasse: -
 | H2 Ebene 0 | WA-KL | 1105Wa 0000000372 |  |  | m² | Zimmer- und Holzbauarbeiten | Wand | Außenwand 7-Schalig | WA-KL |  |  | 0 |  |  |  |  | 0 | AllplanAttributes - Ortscode_Geschoßbezeichnung: E00; Sicherheitsklasse: -
 | H2 Ebene 0 | WA-TL | 1105Wa 0000000376 |  |  | m² | Zimmer- und Holzbauarbeiten | Wand | Außenwand 7-Schalig | WA-TL |  |  | 0 |  |  |  |  | 0 | AllplanAttributes - Ortscode_Geschoßbezeichnung: E00; Sicherheitsklasse: -
 | H2 Ebene 0 | WA-HS | 1105Wa 0000000380 |  |  | m² | Zimmer- und Holzbauarbeiten | Wand | Außenwand 7-Schalig | WA-HS |  |  | 0 |  |  |  |  | 0 | AllplanAttributes - Ortscode_Geschoßbezeichnung: E00; Sicherheitsklasse: -
 | H2 Ebene 0 | WA-LB | 1105Wa 0000001159 |  |  | m² | Trockenbauarbeiten | Wand | Außenwand 7-Schalig | WA-LB |  |  | 0 |  |  |  |  | 0 | AllplanAttributes - Ortscode_Geschoßbezeichnung: E00; Sicherheitsklasse: -
 | H2 Ebene 0 | WA-HD | 1105Wa 0000001155 |  |  | m³ | Zimmer- und Holzbauarbeiten | Wand | Außenwand 7-Schalig | WA-HD |  |  | 0 |  |  |  |  | 0 | AllplanAttributes - Ortscode_Geschoßbezeichnung: E00; Sicherheitsklasse: -
 | H2 Ebene 0 | WA-DL | 1105Wa 0000001135 |  |  | m³ | Zimmer- und Holzbauarbeiten | Wand | Außenwand 7-Schalig | WA-DL |  |  | 0 |  |  |  |  | 0 | AllplanAttributes - Ortscode_Geschoßbezeichnung: E00; Sicherheitsklasse: -
 | H2 Ebene 0 | WA-TP | 1105Wa 0000001139 |  |  | m² | Zimmer- und Holzbauarbeiten | Wand | Außenwand 7-Schalig | WA-TP |  |  | 0 |  |  |  |  | 0 | AllplanAttributes - Ortscode_Geschoßbezeichnung: E00; Sicherheitsklasse: -
 | H2 Ebene 0 | WA-KL | 1105Wa 0000001143 |  |  | m² | Zimmer- und Holzbauarbeiten | Wand | Außenwand 7-Schalig | WA-KL |  |  | 0 |  |  |  |  | 0 | AllplanAttributes - Ortscode_Geschoßbezeichnung: E00; Sicherheitsklasse: -
 | H2 Ebene 0 | WA-TL | 1105Wa 0000001147 |  |  | m² | Zimmer- und Holzbauarbeiten | Wand | Außenwand 7-Schalig | WA-TL |  |  | 0 |  |  |  |  | 0 | AllplanAttributes - Ortscode_Geschoßbezeichnung: E00; Sicherheitsklasse: -
 | H2 Ebene 0 | WA-HS | 1105Wa 0000001151 |  |  | m² | Zimmer- und Holzbauarbeiten | Wand | Außenwand 7-Schalig | WA-HS |  |  | 0 |  |  |  |  | 0 | AllplanAttributes - Ortscode_Geschoßbezeichnung: E00; Sicherheitsklasse: -
 | H2 Ebene 0 | WA-LB | 1105Wa 0000005133 |  |  | m² | Trockenbauarbeiten | Wand | Außenwand 7-Schalig | WA-LB |  |  | 0 |  |  |  |  | 0 | AllplanAttributes - Ortscode_Geschoßbezeichnung: E00; Sicherheitsklasse: -
 | H2 Ebene 0 | WA-HD | 1105Wa 0000005124 |  |  | m³ | Zimmer- und Holzbauarbeiten | Wand | Außenwand 7-Schalig | WA-HD |  |  | 0 |  |  |  |  | 0 | AllplanAttributes - Ortscode_Geschoßbezeichnung: E00; ash D_Detailverweis: DT D; ash D_Plannummer: D1851; Sicherheitsklasse: -
 | H2 Ebene 0 | WA-DL | 1105Wa 0000005115 |  |  | m³ | Zimmer- und Holzbauarbeiten | Wand | Außenwand 7-Schalig | WA-DL |  |  | 0 |  |  |  |  | 0 | AllplanAttributes - Ortscode_Geschoßbezeichnung: E00; Sicherheitsklasse: -
 | H2 Ebene 0 | WA-LB | 1105Wa 0000005106 |  |  | m² | Trockenbauarbeiten | Wand | Außenwand 7-Schalig | WA-LB |  |  | 0 |  |  |  |  | 0 | AllplanAttributes - Ortscode_Geschoßbezeichnung: E00; Sicherheitsklasse: -
 | H2 Ebene 0 | WA-KL | 1105Wa 0000005097 |  |  | m² | Zimmer- und Holzbauarbeiten | Wand | Außenwand 7-Schalig | WA-KL |  |  | 0 |  |  |  |  | 0 | AllplanAttributes - Ortscode_Geschoßbezeichnung: E00; Sicherheitsklasse: -
 | H2 Ebene 0 | WA-TL | 1105Wa 0000005088 |  |  | m² | Zimmer- und Holzbauarbeiten | Wand | Außenwand 7-Schalig | WA-TL |  |  | 0 |  |  |  |  | 0 | AllplanAttributes - Ortscode_Geschoßbezeichnung: E00; Sicherheitsklasse: -
 | H2 Ebene 0 | WA-HS | 1105Wa 0000005079 |  |  | m² | Zimmer- und Holzbauarbeiten | Wand | Außenwand 7-Schalig | WA-HS |  |  | 0 |  |  |  |  | 0 | AllplanAttributes - Ortscode_Geschoßbezeichnung: E00; Sicherheitsklasse: -
 | H2 Ebene 0 | WA-LB | 1105Wa 0000005300 |  |  | m² | Trockenbauarbeiten | Wand | Außenwand 7-Schalig | WA-LB |  |  | 0 |  |  |  |  | 0 | AllplanAttributes - Ortscode_Geschoßbezeichnung: E00; Sicherheitsklasse: -
 | H2 Ebene 0 | WA-HD | 1105Wa 0000005290 |  |  | m³ | Zimmer- und Holzbauarbeiten | Wand | Außenwand 7-Schalig | WA-HD |  |  | 0 |  |  |  |  | 0 | AllplanAttributes - Ortscode_Geschoßbezeichnung: E00; ash D_Detailverweis: DT D; ash D_Plannummer: D1851; Sicherheitsklasse: -
 | H2 Ebene 0 | WA-DL | 1105Wa 0000005280 |  |  | m³ | Zimmer- und Holzbauarbeiten | Wand | Außenwand 7-Schalig | WA-DL |  |  | 0 |  |  |  |  | 0 | AllplanAttributes - Ortscode_Geschoßbezeichnung: E00; Sicherheitsklasse: -
 | H2 Ebene 0 | WA-LB | 1105Wa 0000005270 |  |  | m² | Trockenbauarbeiten | Wand | Außenwand 7-Schalig | WA-LB |  |  | 0 |  |  |  |  | 0 | AllplanAttributes - Ortscode_Geschoßbezeichnung: E00; Sicherheitsklasse: -
 | H2 Ebene 0 | WA-KL | 1105Wa 0000005260 |  |  | m² | Zimmer- und Holzbauarbeiten | Wand | Außenwand 7-Schalig | WA-KL |  |  | 0 |  |  |  |  | 0 | AllplanAttributes - Ortscode_Geschoßbezeichnung: E00; Sicherheitsklasse: -
 | H2 Ebene 0 | WA-TL | 1105Wa 0000005250 |  |  | m² | Zimmer- und Holzbauarbeiten | Wand | Außenwand 7-Schalig | WA-TL |  |  | 0 |  |  |  |  | 0 | AllplanAttributes - Ortscode_Geschoßbezeichnung: E00; Sicherheitsklasse: -
 | H2 Ebene 0 | WA-HS | 1105Wa 0000005240 |  |  | m² | Zimmer- und Holzbauarbeiten | Wand | Außenwand 7-Schalig | WA-HS |  |  | 0 |  |  |  |  | 0 | AllplanAttributes - Ortscode_Geschoßbezeichnung: E00; Sicherheitsklasse: -
 | H2 Ebene 0 | WA-LB | 1105Wa 0000004611 |  |  | m² | Trockenbauarbeiten | Wand | Außenwand 7-Schalig | WA-LB |  |  | 0 |  |  |  |  | 0 | AllplanAttributes - Ortscode_Geschoßbezeichnung: E00; Sicherheitsklasse: -
 | H2 Ebene 0 | WA-HD | 1105Wa 0000004607 |  |  | m³ | Zimmer- und Holzbauarbeiten | Wand | Außenwand 7-Schalig | WA-HD |  |  | 0 |  |  |  |  | 0 | AllplanAttributes - Ortscode_Geschoßbezeichnung: E00; ash D_Detailverweis: DT D; ash D_Plannummer: D1851; Sicherheitsklasse: -
 | H2 Ebene 0 | WA-DL | 1105Wa 0000004603 |  |  | m³ | Zimmer- und Holzbauarbeiten | Wand | Außenwand 7-Schalig | WA-DL |  |  | 0 |  |  |  |  | 0 | AllplanAttributes - Ortscode_Geschoßbezeichnung: E00; Sicherheitsklasse: -
 | H2 Ebene 0 | WA-LB | 1105Wa 0000004599 |  |  | m² | Trockenbauarbeiten | Wand | Außenwand 7-Schalig | WA-LB |  |  | 0 |  |  |  |  | 0 | AllplanAttributes - Ortscode_Geschoßbezeichnung: E00; Sicherheitsklasse: -
 | H2 Ebene 0 | WA-KL | 1105Wa 0000004595 |  |  | m² | Zimmer- und Holzbauarbeiten | Wand | Außenwand 7-Schalig | WA-KL |  |  | 0 |  |  |  |  | 0 | AllplanAttributes - Ortscode_Geschoßbezeichnung: E00; Sicherheitsklasse: -
 | H2 Ebene 0 | WA-TL | 1105Wa 0000004591 |  |  | m² | Zimmer- und Holzbauarbeiten | Wand | Außenwand 7-Schalig | WA-TL |  |  | 0 |  |  |  |  | 0 | AllplanAttributes - Ortscode_Geschoßbezeichnung: E00; Sicherheitsklasse: -
 | H2 Ebene 0 | WA-HS | 1105Wa 0000004587 |  |  | m² | Zimmer- und Holzbauarbeiten | Wand | Außenwand 7-Schalig | WA-HS |  |  | 0 |  |  |  |  | 0 | AllplanAttributes - Ortscode_Geschoßbezeichnung: E00; Sicherheitsklasse: -
 | H2 Ebene 0 | WA-LB | 1105Wa 0000004655 |  |  | m² | Trockenbauarbeiten | Wand | Außenwand 7-Schalig | WA-LB |  |  | 0 |  |  |  |  | 0 | AllplanAttributes - Ortscode_Geschoßbezeichnung: E00; Sicherheitsklasse: -
 | H2 Ebene 0 | WA-HD | 1105Wa 0000004651 |  |  | m³ | Zimmer- und Holzbauarbeiten | Wand | Außenwand 7-Schalig | WA-HD |  |  | 0 |  |  |  |  | 0 | AllplanAttributes - Ortscode_Geschoßbezeichnung: E00; Sicherheitsklasse: -
 | H2 Ebene 0 | WA-DL | 1105Wa 0000004647 |  |  | m³ | Zimmer- und Holzbauarbeiten | Wand | Außenwand 7-Schalig | WA-DL |  |  | 0 |  |  |  |  | 0 | AllplanAttributes - Ortscode_Geschoßbezeichnung: E00; Sicherheitsklasse: -
 | H2 Ebene 0 | WA-LB | 1105Wa 0000004643 |  |  | m² | Trockenbauarbeiten | Wand | Außenwand 7-Schalig | WA-LB |  |  | 0 |  |  |  |  | 0 | AllplanAttributes - Ortscode_Geschoßbezeichnung: E00; Sicherheitsklasse: -
 | H2 Ebene 0 | WA-KL | 1105Wa 0000004639 |  |  | m² | Zimmer- und Holzbauarbeiten | Wand | Außenwand 7-Schalig | WA-KL |  |  | 0 |  |  |  |  | 0 | AllplanAttributes - Ortscode_Geschoßbezeichnung: E00; Sicherheitsklasse: -
 | H2 Ebene 0 | WA-TL | 1105Wa 0000004635 |  |  | m² | Zimmer- und Holzbauarbeiten | Wand | Außenwand 7-Schalig | WA-TL |  |  | 0 |  |  |  |  | 0 | AllplanAttributes - Ortscode_Geschoßbezeichnung: E00; Sicherheitsklasse: -
 | H2 Ebene 0 | WA-HS | 1105Wa 0000004631 |  |  | m² | Zimmer- und Holzbauarbeiten | Wand | Außenwand 7-Schalig | WA-HS |  |  | 0 |  |  |  |  | 0 | AllplanAttributes - Ortscode_Geschoßbezeichnung: E00; Sicherheitsklasse: -
 | H2 Ebene 0 | WA-LB | 1105Wa 0000004406 |  |  | m² | Trockenbauarbeiten | Wand | Außenwand 7-Schalig | WA-LB |  |  | 0 |  |  |  |  | 0 | AllplanAttributes - Ortscode_Geschoßbezeichnung: E00; Sicherheitsklasse: -
 | H2 Ebene 0 | WA-HD | 1105Wa 0000004410 |  |  | m³ | Zimmer- und Holzbauarbeiten | Wand | Außenwand 7-Schalig | WA-HD |  |  | 0 |  |  |  |  | 0 | AllplanAttributes - Ortscode_Geschoßbezeichnung: E00; ash D_Detailverweis: DT D; ash D_Plannummer: D1851; Sicherheitsklasse: -
 | H2 Ebene 0 | WA-DL | 1105Wa 0000004402 |  |  | m³ | Zimmer- und Holzbauarbeiten | Wand | Außenwand 7-Schalig | WA-DL |  |  | 0 |  |  |  |  | 0 | AllplanAttributes - Ortscode_Geschoßbezeichnung: E00; Sicherheitsklasse: -
 | H2 Ebene 0 | WA-LB | 1105Wa 0000004398 |  |  | m² | Trockenbauarbeiten | Wand | Außenwand 7-Schalig | WA-LB |  |  | 0 |  |  |  |  | 0 | AllplanAttributes - Ortscode_Geschoßbezeichnung: E00; Sicherheitsklasse: -
 | H2 Ebene 0 | WA-KL | 1105Wa 0000004394 |  |  | m² | Zimmer- und Holzbauarbeiten | Wand | Außenwand 7-Schalig | WA-KL |  |  | 0 |  |  |  |  | 0 | AllplanAttributes - Ortscode_Geschoßbezeichnung: E00; Sicherheitsklasse: -
 | H2 Ebene 0 | WA-TL | 1105Wa 0000004390 |  |  | m² | Zimmer- und Holzbauarbeiten | Wand | Außenwand 7-Schalig | WA-TL |  |  | 0 |  |  |  |  | 0 | AllplanAttributes - Ortscode_Geschoßbezeichnung: E00; Sicherheitsklasse: -
 | H2 Ebene 0 | WA-HS | 1105Wa 0000004416 |  |  | m² | Zimmer- und Holzbauarbeiten | Wand | Außenwand 7-Schalig | WA-HS |  |  | 0 |  |  |  |  | 0 | AllplanAttributes - Ortscode_Geschoßbezeichnung: E00; Sicherheitsklasse: -
 | H2 Ebene 0 | WA-LB | 1105Wa 0000004443 |  |  | m² | Trockenbauarbeiten | Wand | Außenwand 7-Schalig | WA-LB |  |  | 0 |  |  |  |  | 0 | AllplanAttributes - Ortscode_Geschoßbezeichnung: E00; Sicherheitsklasse: -
 | H2 Ebene 0 | WA-HD | 1105Wa 0000004441 |  |  | m³ | Zimmer- und Holzbauarbeiten | Wand | Außenwand 7-Schalig | WA-HD |  |  | 0 |  |  |  |  | 0 | AllplanAttributes - Ortscode_Geschoßbezeichnung: E00; ash D_Detailverweis: DT D; ash D_Plannummer: D1851; Sicherheitsklasse: -
 | H2 Ebene 0 | WA-DL | 1105Wa 0000004439 |  |  | m³ | Zimmer- und Holzbauarbeiten | Wand | Außenwand 7-Schalig | WA-DL |  |  | 0 |  |  |  |  | 0 | AllplanAttributes - Ortscode_Geschoßbezeichnung: E00; Sicherheitsklasse: -
 | H2 Ebene 0 | WA-LB | 1105Wa 0000004437 |  |  | m² | Trockenbauarbeiten | Wand | Außenwand 7-Schalig | WA-LB |  |  | 0 |  |  |  |  | 0 | AllplanAttributes - Ortscode_Geschoßbezeichnung: E00; Sicherheitsklasse: -
 | H2 Ebene 0 | WA-KL | 1105Wa 0000004435 |  |  | m² | Zimmer- und Holzbauarbeiten | Wand | Außenwand 7-Schalig | WA-KL |  |  | 0 |  |  |  |  | 0 | AllplanAttributes - Ortscode_Geschoßbezeichnung: E00; Sicherheitsklasse: -
 | H2 Ebene 0 | WA-TL | 1105Wa 0000004433 |  |  | m² | Zimmer- und Holzbauarbeiten | Wand | Außenwand 7-Schalig | WA-TL |  |  | 0 |  |  |  |  | 0 | AllplanAttributes - Ortscode_Geschoßbezeichnung: E00; Sicherheitsklasse: -
 | H2 Ebene 0 | WA-HS | 1105Wa 0000004431 |  |  | m² | Zimmer- und Holzbauarbeiten | Wand | Außenwand 7-Schalig | WA-HS |  |  | 0 |  |  |  |  | 0 | AllplanAttributes - Ortscode_Geschoßbezeichnung: E00; Sicherheitsklasse: -
 | H2 Ebene 0 | WA-LB | 1105Wa 0000004803 |  |  | m² | Trockenbauarbeiten | Wand | Außenwand 7-Schalig | WA-LB |  |  | 0 |  |  |  |  | 0 | AllplanAttributes - Ortscode_Geschoßbezeichnung: E00; Sicherheitsklasse: -
 | H2 Ebene 0 | WA-HD | 1105Wa 0000004805 |  |  | m³ | Zimmer- und Holzbauarbeiten | Wand | Außenwand 7-Schalig | WA-HD |  |  | 0 |  |  |  |  | 0 | AllplanAttributes - Ortscode_Geschoßbezeichnung: E00; Sicherheitsklasse: -
 | H2 Ebene 0 | WA-DL | 1105Wa 0000004807 |  |  | m³ | Zimmer- und Holzbauarbeiten | Wand | Außenwand 7-Schalig | WA-DL |  |  | 0 |  |  |  |  | 0 | AllplanAttributes - Ortscode_Geschoßbezeichnung: E00; Sicherheitsklasse: -
 | H2 Ebene 0 | WA-LB | 1105Wa 0000004809 |  |  | m² | Trockenbauarbeiten | Wand | Außenwand 7-Schalig | WA-LB |  |  | 0 |  |  |  |  | 0 | AllplanAttributes - Ortscode_Geschoßbezeichnung: E00; Sicherheitsklasse: -
 | H2 Ebene 0 | WA-KL | 1105Wa 0000004811 |  |  | m² | Zimmer- und Holzbauarbeiten | Wand | Außenwand 7-Schalig | WA-KL |  |  | 0 |  |  |  |  | 0 | AllplanAttributes - Ortscode_Geschoßbezeichnung: E00; Sicherheitsklasse: -
 | H2 Ebene 0 | WA-TL | 1105Wa 0000004813 |  |  | m² | Zimmer- und Holzbauarbeiten | Wand | Außenwand 7-Schalig | WA-TL |  |  | 0 |  |  |  |  | 0 | AllplanAttributes - Ortscode_Geschoßbezeichnung: E00; Sicherheitsklasse: -
 | H2 Ebene 0 | WA-HS | 1105Wa 0000004815 |  |  | m² | Zimmer- und Holzbauarbeiten | Wand | Außenwand 7-Schalig | WA-HS |  |  | 0 |  |  |  |  | 0 | AllplanAttributes - Ortscode_Geschoßbezeichnung: E00; Sicherheitsklasse: -
 | H2 Ebene 0 | WA-LB | 1105Wa 0000003844 |  |  | m² | Trockenbauarbeiten | Wand | Außenwand 7-Schalig | WA-LB |  |  | 0 |  |  |  |  | 0 | AllplanAttributes - Ortscode_Geschoßbezeichnung: E00; Sicherheitsklasse: -
 | H2 Ebene 0 | WA-HD | 1105Wa 0000003834 |  |  | m³ | Zimmer- und Holzbauarbeiten | Wand | Außenwand 7-Schalig | WA-HD |  |  | 0 |  |  |  |  | 0 | AllplanAttributes - Ortscode_Geschoßbezeichnung: E00; ash D_Detailverweis: DT D; ash D_Plannummer: D1851; Sicherheitsklasse: -
 | H2 Ebene 0 | WA-DL | 1105Wa 0000003824 |  |  | m³ | Zimmer- und Holzbauarbeiten | Wand | Außenwand 7-Schalig | WA-DL |  |  | 0 |  |  |  |  | 0 | AllplanAttributes - Ortscode_Geschoßbezeichnung: E00; Sicherheitsklasse: -
 | H2 Ebene 0 | WA-LB | 1105Wa 0000003814 |  |  | m² | Trockenbauarbeiten | Wand | Außenwand 7-Schalig | WA-LB |  |  | 0 |  |  |  |  | 0 | AllplanAttributes - Ortscode_Geschoßbezeichnung: E00; Sicherheitsklasse: -
 | H2 Ebene 0 | WA-KL | 1105Wa 0000003804 |  |  | m² | Zimmer- und Holzbauarbeiten | Wand | Außenwand 7-Schalig | WA-KL |  |  | 0 |  |  |  |  | 0 | AllplanAttributes - Ortscode_Geschoßbezeichnung: E00; Sicherheitsklasse: -
 | H2 Ebene 0 | WA-TL | 1105Wa 0000003794 |  |  | m² | Zimmer- und Holzbauarbeiten | Wand | Außenwand 7-Schalig | WA-TL |  |  | 0 |  |  |  |  | 0 | AllplanAttributes - Ortscode_Geschoßbezeichnung: E00; Sicherheitsklasse: -
 | H2 Ebene 0 | WA-HS | 1105Wa 0000003784 |  |  | m² | Zimmer- und Holzbauarbeiten | Wand | Außenwand 7-Schalig | WA-HS |  |  | 0 |  |  |  |  | 0 | AllplanAttributes - Ortscode_Geschoßbezeichnung: E00; Sicherheitsklasse: -
 | H2 Ebene 0 | WA-LB | 1105Wa 0000001758 |  |  | m² | Trockenbauarbeiten | Wand | Außenwand 7-Schalig | WA-LB |  |  | 0 |  |  |  |  | 0 | AllplanAttributes - Ortscode_Geschoßbezeichnung: E00; Sicherheitsklasse: -
 | H2 Ebene 0 | WA-HD | 1105Wa 0000001756 |  |  | m³ | Zimmer- und Holzbauarbeiten | Wand | Außenwand 7-Schalig | WA-HD |  |  | 0 |  |  |  |  | 0 | AllplanAttributes - Ortscode_Geschoßbezeichnung: E00; Sicherheitsklasse: -
 | H2 Ebene 0 | WA-DL | 1105Wa 0000001754 |  |  | m³ | Zimmer- und Holzbauarbeiten | Wand | Außenwand 7-Schalig | WA-DL |  |  | 0 |  |  |  |  | 0 | AllplanAttributes - Ortscode_Geschoßbezeichnung: E00; Sicherheitsklasse: -
 | H2 Ebene 0 | WA-TP | 1105Wa 0000001752 |  |  | m² | Zimmer- und Holzbauarbeiten | Wand | Außenwand 7-Schalig | WA-TP |  |  | 0 |  |  |  |  | 0 | AllplanAttributes - Ortscode_Geschoßbezeichnung: E00; Sicherheitsklasse: -
 | H2 Ebene 0 | WA-KL | 1105Wa 0000001750 |  |  | m² | Zimmer- und Holzbauarbeiten | Wand | Außenwand 7-Schalig | WA-KL |  |  | 0 |  |  |  |  | 0 | AllplanAttributes - Ortscode_Geschoßbezeichnung: E00; Sicherheitsklasse: -
 | H2 Ebene 0 | WA-TL | 1105Wa 0000001748 |  |  | m² | Zimmer- und Holzbauarbeiten | Wand | Außenwand 7-Schalig | WA-TL |  |  | 0 |  |  |  |  | 0 | AllplanAttributes - Ortscode_Geschoßbezeichnung: E00; Sicherheitsklasse: -
 | H2 Ebene 0 | WA-HS | 1105Wa 0000001746 |  |  | m² | Zimmer- und Holzbauarbeiten | Wand | Außenwand 7-Schalig | WA-HS |  |  | 0 |  |  |  |  | 0 | AllplanAttributes - Ortscode_Geschoßbezeichnung: E00; Sicherheitsklasse: -
 | H2 Ebene 0 | WA-LB | 1105Wa 0000000398 |  |  | m² | Trockenbauarbeiten | Wand | Außenwand 7-Schalig | WA-LB |  |  | 0 |  |  |  |  | 0 | AllplanAttributes - Ortscode_Geschoßbezeichnung: E00; Sicherheitsklasse: -
 | H2 Ebene 0 | WA-HD | 1105Wa 0000000326 |  |  | m³ | Zimmer- und Holzbauarbeiten | Wand | Außenwand 7-Schalig | WA-HD |  |  | 0 |  |  |  |  | 0 | AllplanAttributes - Ortscode_Geschoßbezeichnung: E00; Sicherheitsklasse: -
 | H2 Ebene 0 | WA-DL | 1105Wa 0000000328 |  |  | m³ | Zimmer- und Holzbauarbeiten | Wand | Außenwand 7-Schalig | WA-DL |  |  | 0 |  |  |  |  | 0 | AllplanAttributes - Ortscode_Geschoßbezeichnung: E00; Sicherheitsklasse: -
 | H2 Ebene 0 | WA-TP | 1105Wa 0000000396 |  |  | m² | Zimmer- und Holzbauarbeiten | Wand | Außenwand 7-Schalig | WA-TP |  |  | 0 |  |  |  |  | 0 | AllplanAttributes - Ortscode_Geschoßbezeichnung: E00; Sicherheitsklasse: -
 | H2 Ebene 0 | WA-KL | 1105Wa 0000000394 |  |  | m² | Zimmer- und Holzbauarbeiten | Wand | Außenwand 7-Schalig | WA-KL |  |  | 0 |  |  |  |  | 0 | AllplanAttributes - Ortscode_Geschoßbezeichnung: E00; Sicherheitsklasse: -
 | H2 Ebene 0 | WA-TL | 1105Wa 0000000392 |  |  | m² | Zimmer- und Holzbauarbeiten | Wand | Außenwand 7-Schalig | WA-TL |  |  | 0 |  |  |  |  | 0 | AllplanAttributes - Ortscode_Geschoßbezeichnung: E00; Sicherheitsklasse: -
 | H2 Ebene 0 | WA-HS | 1105Wa 0000000390 |  |  | m² | Zimmer- und Holzbauarbeiten | Wand | Außenwand 7-Schalig | WA-HS |  |  | 0 |  |  |  |  | 0 | AllplanAttributes - Ortscode_Geschoßbezeichnung: E00; Sicherheitsklasse: -
 | H2 Ebene 0 | WA-LB | 1105Wa 0000001119 |  |  | m² | Trockenbauarbeiten | Wand | Außenwand 7-Schalig | WA-LB |  |  | 0 |  |  |  |  | 0 | AllplanAttributes - Ortscode_Geschoßbezeichnung: E00; Sicherheitsklasse: -
 | H2 Ebene 0 | WA-HD | 1105Wa 0000001121 |  |  | m³ | Zimmer- und Holzbauarbeiten | Wand | Außenwand 7-Schalig | WA-HD |  |  | 0 |  |  |  |  | 0 | AllplanAttributes - Ortscode_Geschoßbezeichnung: E00; Sicherheitsklasse: -
 | H2 Ebene 0 | WA-DL | 1105Wa 0000001123 |  |  | m³ | Zimmer- und Holzbauarbeiten | Wand | Außenwand 7-Schalig | WA-DL |  |  | 0 |  |  |  |  | 0 | AllplanAttributes - Ortscode_Geschoßbezeichnung: E00; Sicherheitsklasse: -
 | H2 Ebene 0 | WA-TP | 1105Wa 0000001125 |  |  | m² | Zimmer- und Holzbauarbeiten | Wand | Außenwand 7-Schalig | WA-TP |  |  | 0 |  |  |  |  | 0 | AllplanAttributes - Ortscode_Geschoßbezeichnung: E00; Sicherheitsklasse: -
 | H2 Ebene 0 | WA-KL | 1105Wa 0000001127 |  |  | m² | Zimmer- und Holzbauarbeiten | Wand | Außenwand 7-Schalig | WA-KL |  |  | 0 |  |  |  |  | 0 | AllplanAttributes - Ortscode_Geschoßbezeichnung: E00; Sicherheitsklasse: -
 | H2 Ebene 0 | WA-TL | 1105Wa 0000001129 |  |  | m² | Zimmer- und Holzbauarbeiten | Wand | Außenwand 7-Schalig | WA-TL |  |  | 0 |  |  |  |  | 0 | AllplanAttributes - Ortscode_Geschoßbezeichnung: E00; Sicherheitsklasse: -
 | H2 Ebene 0 | WA-HS | 1105Wa 0000001131 |  |  | m² | Zimmer- und Holzbauarbeiten | Wand | Außenwand 7-Schalig | WA-HS |  |  | 0 |  |  |  |  | 0 | AllplanAttributes - Ortscode_Geschoßbezeichnung: E00; Sicherheitsklasse: -
 | H2 Ebene 0 | WA-LB | 1105Wa 0000001169 |  |  | m² | Trockenbauarbeiten | Wand | Außenwand 7-Schalig | WA-LB |  |  | 0 |  |  |  |  | 0 | AllplanAttributes - Ortscode_Geschoßbezeichnung: E00; Sicherheitsklasse: -
 | H2 Ebene 0 | WA-HD | 1105Wa 0000001087 |  |  | m³ | Zimmer- und Holzbauarbeiten | Wand | Außenwand 7-Schalig | WA-HD |  |  | 0 |  |  |  |  | 0 | AllplanAttributes - Ortscode_Geschoßbezeichnung: E00; Sicherheitsklasse: -
 | H2 Ebene 0 | WA-DL | 1105Wa 0000001089 |  |  | m³ | Zimmer- und Holzbauarbeiten | Wand | Außenwand 7-Schalig | WA-DL |  |  | 0 |  |  |  |  | 0 | AllplanAttributes - Ortscode_Geschoßbezeichnung: E00; Sicherheitsklasse: -
 | H2 Ebene 0 | WA-TP | 1105Wa 0000001167 |  |  | m² | Zimmer- und Holzbauarbeiten | Wand | Außenwand 7-Schalig | WA-TP |  |  | 0 |  |  |  |  | 0 | AllplanAttributes - Ortscode_Geschoßbezeichnung: E00; Sicherheitsklasse: -
 | H2 Ebene 0 | WA-KL | 1105Wa 0000001165 |  |  | m² | Zimmer- und Holzbauarbeiten | Wand | Außenwand 7-Schalig | WA-KL |  |  | 0 |  |  |  |  | 0 | AllplanAttributes - Ortscode_Geschoßbezeichnung: E00; Sicherheitsklasse: -
 | H2 Ebene 0 | WA-TL | 1105Wa 0000001163 |  |  | m² | Zimmer- und Holzbauarbeiten | Wand | Außenwand 7-Schalig | WA-TL |  |  | 0 |  |  |  |  | 0 | AllplanAttributes - Ortscode_Geschoßbezeichnung: E00; Sicherheitsklasse: -
 | H2 Ebene 0 | WA-HS | 1105Wa 0000001161 |  |  | m² | Zimmer- und Holzbauarbeiten | Wand | Außenwand 7-Schalig | WA-HS |  |  | 0 |  |  |  |  | 0 | AllplanAttributes - Ortscode_Geschoßbezeichnung: E00; Sicherheitsklasse: -
 | H2 Ebene 0 | WA-LB | 1105Wa 0000004481 |  |  | m² | Trockenbauarbeiten | Wand | Außenwand 7-Schalig | WA-LB |  |  | 0 |  |  |  |  | 0 | AllplanAttributes - Ortscode_Geschoßbezeichnung: E00; Sicherheitsklasse: -
 | H2 Ebene 0 | WA-HD | 1105Wa 0000004483 |  |  | m³ | Zimmer- und Holzbauarbeiten | Wand | Außenwand 7-Schalig | WA-HD |  |  | 0 |  |  |  |  | 0 | AllplanAttributes - Ortscode_Geschoßbezeichnung: E00; Sicherheitsklasse: -
 | H2 Ebene 0 | WA-DL | 1105Wa 0000004485 |  |  | m³ | Zimmer- und Holzbauarbeiten | Wand | Außenwand 7-Schalig | WA-DL |  |  | 0 |  |  |  |  | 0 | AllplanAttributes - Ortscode_Geschoßbezeichnung: E00; Sicherheitsklasse: -
 | H2 Ebene 0 | WA-TP | 1105Wa 0000004487 |  |  | m² | Trockenbauarbeiten | Wand | Außenwand 7-Schalig | WA-TP |  |  | 0 |  |  |  |  | 0 | AllplanAttributes - Ortscode_Geschoßbezeichnung: E00; Sicherheitsklasse: -
 | H2 Ebene 0 | WA-KL | 1105Wa 0000004489 |  |  | m² | Zimmer- und Holzbauarbeiten | Wand | Außenwand 7-Schalig | WA-KL |  |  | 0 |  |  |  |  | 0 | AllplanAttributes - Ortscode_Geschoßbezeichnung: E00; Sicherheitsklasse: -
 | H2 Ebene 0 | WA-TL | 1105Wa 0000004491 |  |  | m² | Zimmer- und Holzbauarbeiten | Wand | Außenwand 7-Schalig | WA-TL |  |  | 0 |  |  |  |  | 0 | AllplanAttributes - Ortscode_Geschoßbezeichnung: E00; Sicherheitsklasse: -
 | H2 Ebene 0 | WA-HS | 1105Wa 0000004493 |  |  | m² | Zimmer- und Holzbauarbeiten | Wand | Außenwand 7-Schalig | WA-HS |  |  | 0 |  |  |  |  | 0 | AllplanAttributes - Ortscode_Geschoßbezeichnung: E00; Sicherheitsklasse: -
 | H2 Ebene 0 | WA-LB | 1105Wa 0000004509 |  |  | m² | Trockenbauarbeiten | Wand | Außenwand 7-Schalig | WA-LB |  |  | 0 |  |  |  |  | 0 | AllplanAttributes - Ortscode_Geschoßbezeichnung: E00; Sicherheitsklasse: -
 | H2 Ebene 0 | WA-HD | 1105Wa 0000004511 |  |  | m³ | Zimmer- und Holzbauarbeiten | Wand | Außenwand 7-Schalig | WA-HD |  |  | 0 |  |  |  |  | 0 | AllplanAttributes - Ortscode_Geschoßbezeichnung: E00; ash D_Detailverweis: DT D; ash D_Plannummer: D1851; Sicherheitsklasse: -
 | H2 Ebene 0 | WA-DL | 1105Wa 0000004513 |  |  | m³ | Zimmer- und Holzbauarbeiten | Wand | Außenwand 7-Schalig | WA-DL |  |  | 0 |  |  |  |  | 0 | AllplanAttributes - Ortscode_Geschoßbezeichnung: E00; Sicherheitsklasse: -
 | H2 Ebene 0 | WA-LB | 1105Wa 0000004515 |  |  | m² | Trockenbauarbeiten | Wand | Außenwand 7-Schalig | WA-LB |  |  | 0 |  |  |  |  | 0 | AllplanAttributes - Ortscode_Geschoßbezeichnung: E00; Sicherheitsklasse: -
 | H2 Ebene 0 | WA-KL | 1105Wa 0000004517 |  |  | m² | Zimmer- und Holzbauarbeiten | Wand | Außenwand 7-Schalig | WA-KL |  |  | 0 |  |  |  |  | 0 | AllplanAttributes - Ortscode_Geschoßbezeichnung: E00; Sicherheitsklasse: -
 | H2 Ebene 0 | WA-TL | 1105Wa 0000004519 |  |  | m² | Zimmer- und Holzbauarbeiten | Wand | Außenwand 7-Schalig | WA-TL |  |  | 0 |  |  |  |  | 0 | AllplanAttributes - Ortscode_Geschoßbezeichnung: E00; Sicherheitsklasse: -
 | H2 Ebene 0 | WA-HS | 1105Wa 0000004521 |  |  | m² | Zimmer- und Holzbauarbeiten | Wand | Außenwand 7-Schalig | WA-HS |  |  | 0 |  |  |  |  | 0 | AllplanAttributes - Ortscode_Geschoßbezeichnung: E00; Sicherheitsklasse: -
 | H2 Ebene 0 | WA-LB | 1105Wa 0000004583 |  |  | m² | Trockenbauarbeiten | Wand | Außenwand 7-Schalig | WA-LB |  |  | 0 |  |  |  |  | 0 | AllplanAttributes - Ortscode_Geschoßbezeichnung: E00; Sicherheitsklasse: -
 | H2 Ebene 0 | WA-HD | 1105Wa 0000004581 |  |  | m³ | Zimmer- und Holzbauarbeiten | Wand | Außenwand 7-Schalig | WA-HD |  |  | 0 |  |  |  |  | 0 | AllplanAttributes - Ortscode_Geschoßbezeichnung: E00; Sicherheitsklasse: -
 | H2 Ebene 0 | WA-DL | 1105Wa 0000004579 |  |  | m³ | Zimmer- und Holzbauarbeiten | Wand | Außenwand 7-Schalig | WA-DL |  |  | 0 |  |  |  |  | 0 | AllplanAttributes - Ortscode_Geschoßbezeichnung: E00; Sicherheitsklasse: -
 | H2 Ebene 0 | WA-TP | 1105Wa 0000004577 |  |  | m² | Trockenbauarbeiten | Wand | Außenwand 7-Schalig | WA-TP |  |  | 0 |  |  |  |  | 0 | AllplanAttributes - Ortscode_Geschoßbezeichnung: E00; Sicherheitsklasse: -
 | H2 Ebene 0 | WA-KL | 1105Wa 0000004575 |  |  | m² | Zimmer- und Holzbauarbeiten | Wand | Außenwand 7-Schalig | WA-KL |  |  | 0 |  |  |  |  | 0 | AllplanAttributes - Ortscode_Geschoßbezeichnung: E00; Sicherheitsklasse: -
 | H2 Ebene 0 | WA-TL | 1105Wa 0000004573 |  |  | m² | Zimmer- und Holzbauarbeiten | Wand | Außenwand 7-Schalig | WA-TL |  |  | 0 |  |  |  |  | 0 | AllplanAttributes - Ortscode_Geschoßbezeichnung: E00; Sicherheitsklasse: -
 | H2 Ebene 0 | WA-HS | 1105Wa 0000004571 |  |  | m² | Zimmer- und Holzbauarbeiten | Wand | Außenwand 7-Schalig | WA-HS |  |  | 0 |  |  |  |  | 0 | AllplanAttributes - Ortscode_Geschoßbezeichnung: E00; Sicherheitsklasse: -
 | H2 Ebene 0 | WA-LB | 1105Wa 0000004627 |  |  | m² | Trockenbauarbeiten | Wand | Außenwand 7-Schalig | WA-LB |  |  | 0 |  |  |  |  | 0 | AllplanAttributes - Ortscode_Geschoßbezeichnung: E00; Sicherheitsklasse: -
 | H2 Ebene 0 | WA-HD | 1105Wa 0000004625 |  |  | m³ | Zimmer- und Holzbauarbeiten | Wand | Außenwand 7-Schalig | WA-HD |  |  | 0 |  |  |  |  | 0 | AllplanAttributes - Ortscode_Geschoßbezeichnung: E00; Sicherheitsklasse: -
 | H2 Ebene 0 | WA-DL | 1105Wa 0000004623 |  |  | m³ | Zimmer- und Holzbauarbeiten | Wand | Außenwand 7-Schalig | WA-DL |  |  | 0 |  |  |  |  | 0 | AllplanAttributes - Ortscode_Geschoßbezeichnung: E00; Sicherheitsklasse: -
 | H2 Ebene 0 | WA-TP | 1105Wa 0000004621 |  |  | m² | Trockenbauarbeiten | Wand | Außenwand 7-Schalig | WA-TP |  |  | 0 |  |  |  |  | 0 | AllplanAttributes - Ortscode_Geschoßbezeichnung: E00; Sicherheitsklasse: -
 | H2 Ebene 0 | WA-KL | 1105Wa 0000004619 |  |  | m² | Zimmer- und Holzbauarbeiten | Wand | Außenwand 7-Schalig | WA-KL |  |  | 0 |  |  |  |  | 0 | AllplanAttributes - Ortscode_Geschoßbezeichnung: E00; Sicherheitsklasse: -
 | H2 Ebene 0 | WA-TL | 1105Wa 0000004617 |  |  | m² | Zimmer- und Holzbauarbeiten | Wand | Außenwand 7-Schalig | WA-TL |  |  | 0 |  |  |  |  | 0 | AllplanAttributes - Ortscode_Geschoßbezeichnung: E00; Sicherheitsklasse: -
 | H2 Ebene 0 | WA-HS | 1105Wa 0000004615 |  |  | m² | Zimmer- und Holzbauarbeiten | Wand | Außenwand 7-Schalig | WA-HS |  |  | 0 |  |  |  |  | 0 | AllplanAttributes - Ortscode_Geschoßbezeichnung: E00; Sicherheitsklasse: -
 | H2 Ebene 0 | WA-LB | 1105Wa 0000004471 |  |  | m² | Trockenbauarbeiten | Wand | Außenwand 7-Schalig | WA-LB |  |  | 0 |  |  |  |  | 0 | AllplanAttributes - Ortscode_Geschoßbezeichnung: E00; Sicherheitsklasse: -
 | H2 Ebene 0 | WA-HD | 1105Wa 0000004469 |  |  | m³ | Zimmer- und Holzbauarbeiten | Wand | Außenwand 7-Schalig | WA-HD |  |  | 0 |  |  |  |  | 0 | AllplanAttributes - Ortscode_Geschoßbezeichnung: E00; Sicherheitsklasse: -
 | H2 Ebene 0 | WA-DL | 1105Wa 0000004467 |  |  | m³ | Zimmer- und Holzbauarbeiten | Wand | Außenwand 7-Schalig | WA-DL |  |  | 0 |  |  |  |  | 0 | AllplanAttributes - Ortscode_Geschoßbezeichnung: E00; Sicherheitsklasse: -
 | H2 Ebene 0 | WA-TP | 1105Wa 0000004465 |  |  | m² | Trockenbauarbeiten | Wand | Außenwand 7-Schalig | WA-TP |  |  | 0 |  |  |  |  | 0 | AllplanAttributes - Ortscode_Geschoßbezeichnung: E00; Sicherheitsklasse: -
 | H2 Ebene 0 | WA-KL | 1105Wa 0000004463 |  |  | m² | Zimmer- und Holzbauarbeiten | Wand | Außenwand 7-Schalig | WA-KL |  |  | 0 |  |  |  |  | 0 | AllplanAttributes - Ortscode_Geschoßbezeichnung: E00; Sicherheitsklasse: -
 | H2 Ebene 0 | WA-TL | 1105Wa 0000004461 |  |  | m² | Zimmer- und Holzbauarbeiten | Wand | Außenwand 7-Schalig | WA-TL |  |  | 0 |  |  |  |  | 0 | AllplanAttributes - Ortscode_Geschoßbezeichnung: E00; Sicherheitsklasse: -
 | H2 Ebene 0 | WA-HS | 1105Wa 0000004459 |  |  | m² | Zimmer- und Holzbauarbeiten | Wand | Außenwand 7-Schalig | WA-HS |  |  | 0 |  |  |  |  | 0 | AllplanAttributes - Ortscode_Geschoßbezeichnung: E00; Sicherheitsklasse: -
 | H2 Ebene 0 | WA-LB | 1105Wa 0000100155 |  |  | m² | Trockenbauarbeiten | Wand | Außenwand 7-Schalig | WA-LB |  |  | 0 |  |  |  |  | 0 | AllplanAttributes - Ortscode_Geschoßbezeichnung: E00; Sicherheitsklasse: -
 | H2 Ebene 0 | WA-HD | 1105Wa 0000100156 |  |  | m³ | Zimmer- und Holzbauarbeiten | Wand | Außenwand 7-Schalig | WA-HD |  |  | 0 |  |  |  |  | 0 | AllplanAttributes - Ortscode_Geschoßbezeichnung: E00; Sicherheitsklasse: -
 | H2 Ebene 0 | WA-DL | 1105Wa 0000100157 |  |  | m³ | Zimmer- und Holzbauarbeiten | Wand | Außenwand 7-Schalig | WA-DL |  |  | 0 |  |  |  |  | 0 | AllplanAttributes - Ortscode_Geschoßbezeichnung: E00; Sicherheitsklasse: -
 | H2 Ebene 0 | WA-TP | 1105Wa 0000100158 |  |  | m² | Zimmer- und Holzbauarbeiten | Wand | Außenwand 7-Schalig | WA-TP |  |  | 0 |  |  |  |  | 0 | AllplanAttributes - Ortscode_Geschoßbezeichnung: E00; Sicherheitsklasse: -
 | H2 Ebene 0 | WA-KL | 1105Wa 0000100159 |  |  | m² | Zimmer- und Holzbauarbeiten | Wand | Außenwand 7-Schalig | WA-KL |  |  | 0 |  |  |  |  | 0 | AllplanAttributes - Ortscode_Geschoßbezeichnung: E00; Sicherheitsklasse: -
 | H2 Ebene 0 | WA-TL | 1105Wa 0000100160 |  |  | m² | Zimmer- und Holzbauarbeiten | Wand | Außenwand 7-Schalig | WA-TL |  |  | 0 |  |  |  |  | 0 | AllplanAttributes - Ortscode_Geschoßbezeichnung: E00; Sicherheitsklasse: -
 | H2 Ebene 0 | WA-HS | 1105Wa 0000100161 |  |  | m² | Zimmer- und Holzbauarbeiten | Wand | Außenwand 7-Schalig | WA-HS |  |  | 0 |  |  |  |  | 0 | AllplanAttributes - Ortscode_Geschoßbezeichnung: E00; Sicherheitsklasse: -
 | H2 Ebene 0 | WA-LB | 1105Wa 0000004830 |  |  | m² | Trockenbauarbeiten | Wand | Außenwand 7-Schalig | WA-LB |  |  | 0 |  |  |  |  | 0 | AllplanAttributes - Ortscode_Geschoßbezeichnung: E00; Sicherheitsklasse: -
 | H2 Ebene 0 | WA-HD | 1105Wa 0000004828 |  |  | m³ | Zimmer- und Holzbauarbeiten | Wand | Außenwand 7-Schalig | WA-HD |  |  | 0 |  |  |  |  | 0 | AllplanAttributes - Ortscode_Geschoßbezeichnung: E00; Sicherheitsklasse: -
 | H2 Ebene 0 | WA-DL | 1105Wa 0000004826 |  |  | m³ | Zimmer- und Holzbauarbeiten | Wand | Außenwand 7-Schalig | WA-DL |  |  | 0 |  |  |  |  | 0 | AllplanAttributes - Ortscode_Geschoßbezeichnung: E00; Sicherheitsklasse: -
 | H2 Ebene 0 | WA-TP | 1105Wa 0000004824 |  |  | m² | Trockenbauarbeiten | Wand | Außenwand 7-Schalig | WA-TP |  |  | 0 |  |  |  |  | 0 | AllplanAttributes - Ortscode_Geschoßbezeichnung: E00; Sicherheitsklasse: -
 | H2 Ebene 0 | WA-KL | 1105Wa 0000004822 |  |  | m² | Zimmer- und Holzbauarbeiten | Wand | Außenwand 7-Schalig | WA-KL |  |  | 0 |  |  |  |  | 0 | AllplanAttributes - Ortscode_Geschoßbezeichnung: E00; Sicherheitsklasse: -
 | H2 Ebene 0 | WA-TL | 1105Wa 0000004820 |  |  | m² | Zimmer- und Holzbauarbeiten | Wand | Außenwand 7-Schalig | WA-TL |  |  | 0 |  |  |  |  | 0 | AllplanAttributes - Ortscode_Geschoßbezeichnung: E00; Sicherheitsklasse: -
 | H2 Ebene 0 | WA-HS | 1105Wa 0000004818 |  |  | m² | Zimmer- und Holzbauarbeiten | Wand | Außenwand 7-Schalig | WA-HS |  |  | 0 |  |  |  |  | 0 | AllplanAttributes - Ortscode_Geschoßbezeichnung: E00; Sicherheitsklasse: -
 | H2 Ebene 0 | WA-LB | 1105Wa 0000004865 |  |  | m² | Trockenbauarbeiten | Wand | Außenwand 7-Schalig | WA-LB |  |  | 0 |  |  |  |  | 0 | AllplanAttributes - Ortscode_Geschoßbezeichnung: E00; Sicherheitsklasse: -
 | H2 Ebene 0 | WA-HD | 1105Wa 0000004860 |  |  | m³ | Zimmer- und Holzbauarbeiten | Wand | Außenwand 7-Schalig | WA-HD |  |  | 0 |  |  |  |  | 0 | AllplanAttributes - Ortscode_Geschoßbezeichnung: E00; Sicherheitsklasse: -
 | H2 Ebene 0 | WA-DL | 1105Wa 0000004855 |  |  | m³ | Zimmer- und Holzbauarbeiten | Wand | Außenwand 7-Schalig | WA-DL |  |  | 0 |  |  |  |  | 0 | AllplanAttributes - Ortscode_Geschoßbezeichnung: E00; Sicherheitsklasse: -
 | H2 Ebene 0 | WA-LB | 1105Wa 0000004850 |  |  | m² | Trockenbauarbeiten | Wand | Außenwand 7-Schalig | WA-LB |  |  | 0 |  |  |  |  | 0 | AllplanAttributes - Ortscode_Geschoßbezeichnung: E00; Sicherheitsklasse: -
 | H2 Ebene 0 | WA-KL | 1105Wa 0000004845 |  |  | m² | Zimmer- und Holzbauarbeiten | Wand | Außenwand 7-Schalig | WA-KL |  |  | 0 |  |  |  |  | 0 | AllplanAttributes - Ortscode_Geschoßbezeichnung: E00; Sicherheitsklasse: -
 | H2 Ebene 0 | WA-TL | 1105Wa 0000004840 |  |  | m² | Zimmer- und Holzbauarbeiten | Wand | Außenwand 7-Schalig | WA-TL |  |  | 0 |  |  |  |  | 0 | AllplanAttributes - Ortscode_Geschoßbezeichnung: E00; Sicherheitsklasse: -
 | H2 Ebene 0 | WA-HS | 1105Wa 0000004835 |  |  | m² | Zimmer- und Holzbauarbeiten | Wand | Außenwand 7-Schalig | WA-HS |  |  | 0 |  |  |  |  | 0 | AllplanAttributes - Ortscode_Geschoßbezeichnung: E00; Sicherheitsklasse: -
 | H2 Ebene 0 | WA-LB | 1105Wa 0000004187 |  |  | m² | Trockenbauarbeiten | Wand | Außenwand 7-Schalig | WA-LB |  |  | 0 |  |  |  |  | 0 | AllplanAttributes - Ortscode_Geschoßbezeichnung: E00; Sicherheitsklasse: -
 | H2 Ebene 0 | WA-HD | 1105Wa 0000004189 |  |  | m³ | Zimmer- und Holzbauarbeiten | Wand | Außenwand 7-Schalig | WA-HD |  |  | 0 |  |  |  |  | 0 | AllplanAttributes - Ortscode_Geschoßbezeichnung: E00; Sicherheitsklasse: -
 | H2 Ebene 0 | WA-DL | 1105Wa 0000004191 |  |  | m³ | Zimmer- und Holzbauarbeiten | Wand | Außenwand 7-Schalig | WA-DL |  |  | 0 |  |  |  |  | 0 | AllplanAttributes - Ortscode_Geschoßbezeichnung: E00; Sicherheitsklasse: -
 | H2 Ebene 0 | WA-TP | 1105Wa 0000004193 |  |  | m² | Trockenbauarbeiten | Wand | Außenwand 7-Schalig | WA-TP |  |  | 0 |  |  |  |  | 0 | AllplanAttributes - Ortscode_Geschoßbezeichnung: E00; Sicherheitsklasse: -
 | H2 Ebene 0 | WA-KL | 1105Wa 0000004195 |  |  | m² | Zimmer- und Holzbauarbeiten | Wand | Außenwand 7-Schalig | WA-KL |  |  | 0 |  |  |  |  | 0 | AllplanAttributes - Ortscode_Geschoßbezeichnung: E00; Sicherheitsklasse: -
 | H2 Ebene 0 | WA-TL | 1105Wa 0000004197 |  |  | m² | Zimmer- und Holzbauarbeiten | Wand | Außenwand 7-Schalig | WA-TL |  |  | 0 |  |  |  |  | 0 | AllplanAttributes - Ortscode_Geschoßbezeichnung: E00; Sicherheitsklasse: -
 | H2 Ebene 0 | WA-HS | 1105Wa 0000004199 |  |  | m² | Zimmer- und Holzbauarbeiten | Wand | Außenwand 7-Schalig | WA-HS |  |  | 0 |  |  |  |  | 0 | AllplanAttributes - Ortscode_Geschoßbezeichnung: E00; Sicherheitsklasse: -
 | H2 Ebene 0 | WA-LB | 1105Wa 0000004538 |  |  | m² | Trockenbauarbeiten | Wand | Außenwand 7-Schalig | WA-LB |  |  | 0 |  |  |  |  | 0 | AllplanAttributes - Ortscode_Geschoßbezeichnung: E00; Sicherheitsklasse: -
 | H2 Ebene 0 | WA-HD | 1105Wa 0000004543 |  |  | m³ | Zimmer- und Holzbauarbeiten | Wand | Außenwand 7-Schalig | WA-HD |  |  | 0 |  |  |  |  | 0 | AllplanAttributes - Ortscode_Geschoßbezeichnung: E00; Sicherheitsklasse: -
 | H2 Ebene 0 | WA-DL | 1105Wa 0000004548 |  |  | m³ | Zimmer- und Holzbauarbeiten | Wand | Außenwand 7-Schalig | WA-DL |  |  | 0 |  |  |  |  | 0 | AllplanAttributes - Ortscode_Geschoßbezeichnung: E00; Sicherheitsklasse: -
 | H2 Ebene 0 | WA-LB | 1105Wa 0000004553 |  |  | m² | Trockenbauarbeiten | Wand | Außenwand 7-Schalig | WA-LB |  |  | 0 |  |  |  |  | 0 | AllplanAttributes - Ortscode_Geschoßbezeichnung: E00; Sicherheitsklasse: -
 | H2 Ebene 0 | WA-KL | 1105Wa 0000004558 |  |  | m² | Zimmer- und Holzbauarbeiten | Wand | Außenwand 7-Schalig | WA-KL |  |  | 0 |  |  |  |  | 0 | AllplanAttributes - Ortscode_Geschoßbezeichnung: E00; Sicherheitsklasse: -
 | H2 Ebene 0 | WA-TL | 1105Wa 0000004563 |  |  | m² | Zimmer- und Holzbauarbeiten | Wand | Außenwand 7-Schalig | WA-TL |  |  | 0 |  |  |  |  | 0 | AllplanAttributes - Ortscode_Geschoßbezeichnung: E00; Sicherheitsklasse: -
 | H2 Ebene 0 | WA-HS | 1105Wa 0000004568 |  |  | m² | Zimmer- und Holzbauarbeiten | Wand | Außenwand 7-Schalig | WA-HS |  |  | 0 |  |  |  |  | 0 | AllplanAttributes - Ortscode_Geschoßbezeichnung: E00; Sicherheitsklasse: -
 | H2 Ebene 0 | WA-LB | 1105Wa 0811529075 |  |  | m² | Trockenbauarbeiten | Wand | Außenwand 7-Schalig | WA-LB |  |  | 0 |  |  |  |  | 0 | AllplanAttributes - Ortscode_Geschoßbezeichnung: E00; Sicherheitsklasse: -
 | H2 Ebene 0 | WA-HD | 1105Wa 0811529074 |  |  | m³ | Zimmer- und Holzbauarbeiten | Wand | Außenwand 7-Schalig | WA-HD |  |  | 0 |  |  |  |  | 0 | AllplanAttributes - Ortscode_Geschoßbezeichnung: E00; Sicherheitsklasse: -
 | H2 Ebene 0 | WA-DL | 1105Wa 0811529073 |  |  | m³ | Zimmer- und Holzbauarbeiten | Wand | Außenwand 7-Schalig | WA-DL |  |  | 0 |  |  |  |  | 0 | AllplanAttributes - Ortscode_Geschoßbezeichnung: E00; Sicherheitsklasse: -
 | H2 Ebene 0 | WA-LB | 1105Wa 0811529072 |  |  | m² | Trockenbauarbeiten | Wand | Außenwand 7-Schalig | WA-LB |  |  | 0 |  |  |  |  | 0 | AllplanAttributes - Ortscode_Geschoßbezeichnung: E00; Sicherheitsklasse: -
 | H2 Ebene 0 | WA-KL | 1105Wa 0811529071 |  |  | m² | Zimmer- und Holzbauarbeiten | Wand | Außenwand 7-Schalig | WA-KL |  |  | 0 |  |  |  |  | 0 | AllplanAttributes - Ortscode_Geschoßbezeichnung: E00; Sicherheitsklasse: -
 | H2 Ebene 0 | WA-TL | 1105Wa 0811529070 |  |  | m² | Zimmer- und Holzbauarbeiten | Wand | Außenwand 7-Schalig | WA-TL |  |  | 0 |  |  |  |  | 0 | AllplanAttributes - Ortscode_Geschoßbezeichnung: E00; Sicherheitsklasse: -
 | H2 Ebene 0 | WA-HS | 1105Wa 0811529069 |  |  | m² | Zimmer- und Holzbauarbeiten | Wand | Außenwand 7-Schalig | WA-HS |  |  | 0 |  |  |  |  | 0 | AllplanAttributes - Ortscode_Geschoßbezeichnung: E00; Sicherheitsklasse: -
 | H2 Ebene 0 | WA-LB | 1105Wa 0811564258 |  |  | m² | Trockenbauarbeiten | Wand | Außenwand 7-Schalig | WA-LB |  |  | 0 |  |  |  |  | 0 | AllplanAttributes - Ortscode_Geschoßbezeichnung: E00; Sicherheitsklasse: -
 | H2 Ebene 0 | WA-HD | 1105Wa 0811564257 |  |  | m³ | Zimmer- und Holzbauarbeiten | Wand | Außenwand 7-Schalig | WA-HD |  |  | 0 |  |  |  |  | 0 | AllplanAttributes - Ortscode_Geschoßbezeichnung: E00; Sicherheitsklasse: -
 | H2 Ebene 0 | WA-DL | 1105Wa 0811564256 |  |  | m³ | Zimmer- und Holzbauarbeiten | Wand | Außenwand 7-Schalig | WA-DL |  |  | 0 |  |  |  |  | 0 | AllplanAttributes - Ortscode_Geschoßbezeichnung: E00; Sicherheitsklasse: -
 | H2 Ebene 0 | WA-TP | 1105Wa 0811564255 |  |  | m² | Zimmer- und Holzbauarbeiten | Wand | Außenwand 7-Schalig | WA-TP |  |  | 0 |  |  |  |  | 0 | AllplanAttributes - Ortscode_Geschoßbezeichnung: E00; Sicherheitsklasse: -
 | H2 Ebene 0 | WA-KL | 1105Wa 0811564254 |  |  | m² | Zimmer- und Holzbauarbeiten | Wand | Außenwand 7-Schalig | WA-KL |  |  | 0 |  |  |  |  | 0 | AllplanAttributes - Ortscode_Geschoßbezeichnung: E00; Sicherheitsklasse: -
 | H2 Ebene 0 | WA-TL | 1105Wa 0811564253 |  |  | m² | Zimmer- und Holzbauarbeiten | Wand | Außenwand 7-Schalig | WA-TL |  |  | 0 |  |  |  |  | 0 | AllplanAttributes - Ortscode_Geschoßbezeichnung: E00; Sicherheitsklasse: -
 | H2 Ebene 0 | WA-HS | 1105Wa 0811564252 |  |  | m² | Zimmer- und Holzbauarbeiten | Wand | Außenwand 7-Schalig | WA-HS |  |  | 0 |  |  |  |  | 0 | AllplanAttributes - Ortscode_Geschoßbezeichnung: E00; Sicherheitsklasse: -
 | H2 Ebene 0 | WA-LB | 1105Wa 0000004015 |  |  | m² | Trockenbauarbeiten | Wand | Außenwand 7-Schalig | WA-LB |  |  | 0 |  |  |  |  | 0 | AllplanAttributes - Ortscode_Geschoßbezeichnung: E00; Sicherheitsklasse: -
 | H2 Ebene 0 | WA-HD | 1105Wa 0000004020 |  |  | m³ | Zimmer- und Holzbauarbeiten | Wand | Außenwand 7-Schalig | WA-HD |  |  | 0 |  |  |  |  | 0 | AllplanAttributes - Ortscode_Geschoßbezeichnung: E00; ash D_Detailverweis: DT D; ash D_Plannummer: D1851; Sicherheitsklasse: -
 | H2 Ebene 0 | WA-DL | 1105Wa 0000004024 |  |  | m³ | Zimmer- und Holzbauarbeiten | Wand | Außenwand 7-Schalig | WA-DL |  |  | 0 |  |  |  |  | 0 | AllplanAttributes - Ortscode_Geschoßbezeichnung: E00; Sicherheitsklasse: -
 | H2 Ebene 0 | WA-LB | 1105Wa 0000004029 |  |  | m² | Trockenbauarbeiten | Wand | Außenwand 7-Schalig | WA-LB |  |  | 0 |  |  |  |  | 0 | AllplanAttributes - Ortscode_Geschoßbezeichnung: E00; Sicherheitsklasse: -
 | H2 Ebene 0 | WA-KL | 1105Wa 0000004034 |  |  | m² | Zimmer- und Holzbauarbeiten | Wand | Außenwand 7-Schalig | WA-KL |  |  | 0 |  |  |  |  | 0 | AllplanAttributes - Ortscode_Geschoßbezeichnung: E00; Sicherheitsklasse: -
 | H2 Ebene 0 | WA-TL | 1105Wa 0000004039 |  |  | m² | Zimmer- und Holzbauarbeiten | Wand | Außenwand 7-Schalig | WA-TL |  |  | 0 |  |  |  |  | 0 | AllplanAttributes - Ortscode_Geschoßbezeichnung: E00; Sicherheitsklasse: -
 | H2 Ebene 0 | WA-HS | 1105Wa 0000004044 |  |  | m² | Zimmer- und Holzbauarbeiten | Wand | Außenwand 7-Schalig | WA-HS |  |  | 0 |  |  |  |  | 0 | AllplanAttributes - Ortscode_Geschoßbezeichnung: E00; Sicherheitsklasse: -
 | H2 Ebene 0 | WA-LB | 1105Wa 0000005175 |  |  | m² | Trockenbauarbeiten | Wand | Außenwand 7-Schalig | WA-LB |  |  | 0 |  |  |  |  | 0 | AllplanAttributes - Ortscode_Geschoßbezeichnung: E00; Sicherheitsklasse: -
 | H2 Ebene 0 | WA-HD | 1105Wa 0000005180 |  |  | m³ | Zimmer- und Holzbauarbeiten | Wand | Außenwand 7-Schalig | WA-HD |  |  | 0 |  |  |  |  | 0 | AllplanAttributes - Ortscode_Geschoßbezeichnung: E00; ash D_Detailverweis: DT D; ash D_Plannummer: D1851; Sicherheitsklasse: -
 | H2 Ebene 0 | WA-DL | 1105Wa 0000005184 |  |  | m³ | Zimmer- und Holzbauarbeiten | Wand | Außenwand 7-Schalig | WA-DL |  |  | 0 |  |  |  |  | 0 | AllplanAttributes - Ortscode_Geschoßbezeichnung: E00; Sicherheitsklasse: -
 | H2 Ebene 0 | WA-LB | 1105Wa 0000005189 |  |  | m² | Trockenbauarbeiten | Wand | Außenwand 7-Schalig | WA-LB |  |  | 0 |  |  |  |  | 0 | AllplanAttributes - Ortscode_Geschoßbezeichnung: E00; Sicherheitsklasse: -
 | H2 Ebene 0 | WA-KL | 1105Wa 0000005194 |  |  | m² | Zimmer- und Holzbauarbeiten | Wand | Außenwand 7-Schalig | WA-KL |  |  | 0 |  |  |  |  | 0 | AllplanAttributes - Ortscode_Geschoßbezeichnung: E00; Sicherheitsklasse: -
 | H2 Ebene 0 | WA-TL | 1105Wa 0000005199 |  |  | m² | Zimmer- und Holzbauarbeiten | Wand | Außenwand 7-Schalig | WA-TL |  |  | 0 |  |  |  |  | 0 | AllplanAttributes - Ortscode_Geschoßbezeichnung: E00; Sicherheitsklasse: -
 | H2 Ebene 0 | WA-HS | 1105Wa 0000005170 |  |  | m² | Zimmer- und Holzbauarbeiten | Wand | Außenwand 7-Schalig | WA-HS |  |  | 0 |  |  |  |  | 0 | AllplanAttributes - Ortscode_Geschoßbezeichnung: E00; Sicherheitsklasse: -
 | H2 Ebene 0 | WA-LB | 1105Wa 0000005305 |  |  | m² | Trockenbauarbeiten | Wand | Außenwand 7-Schalig | WA-LB |  |  | 0 |  |  |  |  | 0 | AllplanAttributes - Ortscode_Geschoßbezeichnung: E00; Sicherheitsklasse: -
 | H2 Ebene 0 | WA-HD | 1105Wa 0000005310 |  |  | m³ | Zimmer- und Holzbauarbeiten | Wand | Außenwand 7-Schalig | WA-HD |  |  | 0 |  |  |  |  | 0 | AllplanAttributes - Ortscode_Geschoßbezeichnung: E00; Sicherheitsklasse: -
 | H2 Ebene 0 | WA-DL | 1105Wa 0000005315 |  |  | m³ | Zimmer- und Holzbauarbeiten | Wand | Außenwand 7-Schalig | WA-DL |  |  | 0 |  |  |  |  | 0 | AllplanAttributes - Ortscode_Geschoßbezeichnung: E00; Sicherheitsklasse: -
 | H2 Ebene 0 | WA-DL | 1105Wa 0000005320 |  |  | m³ | Zimmer- und Holzbauarbeiten | Wand | Außenwand 7-Schalig | WA-DL |  |  | 0 |  |  |  |  | 0 | AllplanAttributes - Ortscode_Geschoßbezeichnung: E00; Sicherheitsklasse: -
 | H2 Ebene 0 | WA-LB | 1105Wa 0000005325 |  |  | m² | Trockenbauarbeiten | Wand | Außenwand 7-Schalig | WA-LB |  |  | 0 |  |  |  |  | 0 | AllplanAttributes - Ortscode_Geschoßbezeichnung: E00; Sicherheitsklasse: -
 | H2 Ebene 0 | WA-KL | 1105Wa 0000005330 |  |  | m² | Zimmer- und Holzbauarbeiten | Wand | Außenwand 7-Schalig | WA-KL |  |  | 0 |  |  |  |  | 0 | AllplanAttributes - Ortscode_Geschoßbezeichnung: E00; Sicherheitsklasse: -
 | H2 Ebene 0 | WA-TL | 1105Wa 0000005335 |  |  | m² | Zimmer- und Holzbauarbeiten | Wand | Außenwand 7-Schalig | WA-TL |  |  | 0 |  |  |  |  | 0 | AllplanAttributes - Ortscode_Geschoßbezeichnung: E00; Sicherheitsklasse: -
 | H2 Ebene 0 | WA-HS | 1105Wa 0811581132 |  |  | m² | Zimmer- und Holzbauarbeiten | Wand | Außenwand 7-Schalig | WA-HS |  |  | 0 |  |  |  |  | 0 | AllplanAttributes - Ortscode_Geschoßbezeichnung: E00; Sicherheitsklasse: -
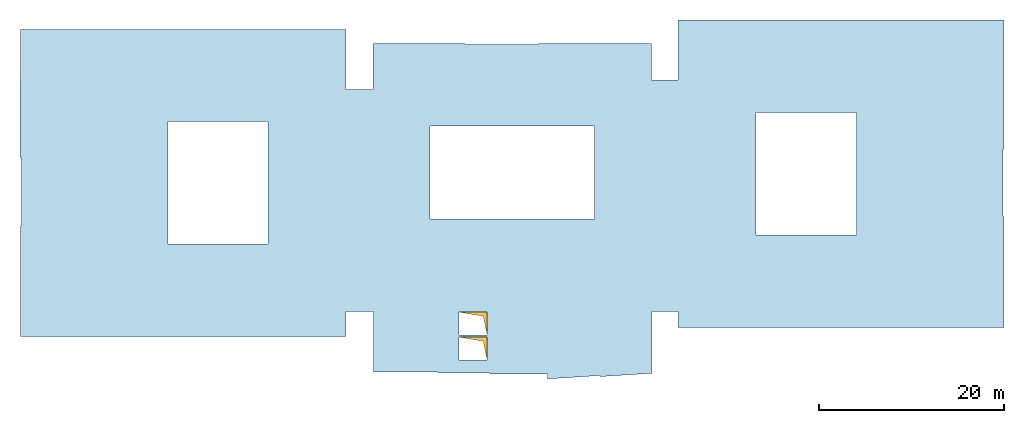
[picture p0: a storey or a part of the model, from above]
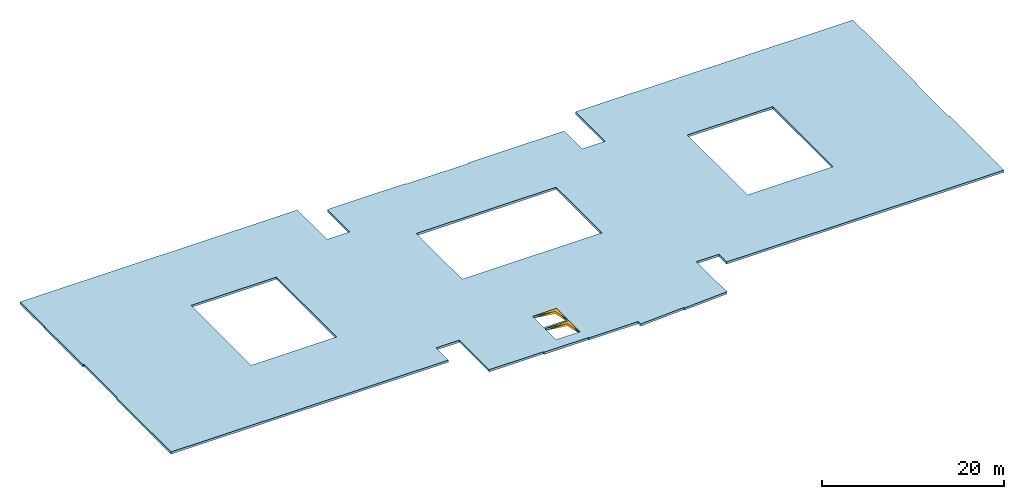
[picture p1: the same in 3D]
Properties of the parts of a building model (IFC4), part 70 of 80

# IfcWall (6826)
Name | In | Material | Allright_Bauteil_ID | 2D Interaktion | Codetext | Abrechnungsart | Gewerk | Objektname | Bezeichnung | AllplanAttributes, Material | Typ = SurfaceSpreadOfFlame | Brandschutzklasse | OKFF | P_ID | Status | LoadBearing | IsExternal | FireRating | ThermalTransmittance (W/K/m2) | Combustible | AcousticRating | Compartmentation | Reference
 | H2 Ebene 0 | WA-LB | 1105Wa 0000004689 |  |  | m² | Trockenbauarbeiten | Wand | Außenwand 7-Schalig | WA-LB |  |  | 0 |  |  |  |  | 0 | AllplanAttributes - Ortscode_Geschoßbezeichnung: E00; Sicherheitsklasse: -
 | H2 Ebene 0 | WA-HD | 1105Wa 0000004693 |  |  | m³ | Zimmer- und Holzbauarbeiten | Wand | Außenwand 7-Schalig | WA-HD |  |  | 0 |  |  |  |  | 0 | AllplanAttributes - Ortscode_Geschoßbezeichnung: E00; Sicherheitsklasse: -
 | H2 Ebene 0 | WA-DL | 1105Wa 0000004697 |  |  | m³ | Zimmer- und Holzbauarbeiten | Wand | Außenwand 7-Schalig | WA-DL |  |  | 0 |  |  |  |  | 0 | AllplanAttributes - Ortscode_Geschoßbezeichnung: E00; Sicherheitsklasse: -
 | H2 Ebene 0 | WA-LB | 1105Wa 0000004701 |  |  | m² | Trockenbauarbeiten | Wand | Außenwand 7-Schalig | WA-LB |  |  | 0 |  |  |  |  | 0 | AllplanAttributes - Ortscode_Geschoßbezeichnung: E00; Sicherheitsklasse: -
 | H2 Ebene 0 | WA-KL | 1105Wa 0000004705 |  |  | m² | Zimmer- und Holzbauarbeiten | Wand | Außenwand 7-Schalig | WA-KL |  |  | 0 |  |  |  |  | 0 | AllplanAttributes - Ortscode_Geschoßbezeichnung: E00; Sicherheitsklasse: -
 | H2 Ebene 0 | WA-TL | 1105Wa 0000004709 |  |  | m² | Zimmer- und Holzbauarbeiten | Wand | Außenwand 7-Schalig | WA-TL |  |  | 0 |  |  |  |  | 0 | AllplanAttributes - Ortscode_Geschoßbezeichnung: E00; Sicherheitsklasse: -
 | H2 Ebene 0 | WA-HS | 1105Wa 0000004713 |  |  | m² | Zimmer- und Holzbauarbeiten | Wand | Außenwand 7-Schalig | WA-HS |  |  | 0 |  |  |  |  | 0 | AllplanAttributes - Ortscode_Geschoßbezeichnung: E00; Sicherheitsklasse: -
 | H2 Ebene 0 | WA-LB | 1105Wa 0811557440 | yes |  | m² | Trockenbauarbeiten | Wand | Außenwand 7-Schalig | WA-LB |  |  | 0 |  | NEW |  |  | 0 | AllplanAttributes - Ortscode_Geschoßbezeichnung: E00; Sicherheitsklasse: -
 | H2 Ebene 0 | WA-HD | 1105Wa 0811557437 | yes |  | m³ | Zimmer- und Holzbauarbeiten | Wand | Außenwand 7-Schalig | WA-HD |  |  | 0 |  | NEW |  |  | 0 | AllplanAttributes - Ortscode_Geschoßbezeichnung: E00; ash D_Detailverweis: DT F; ash D_Plannummer: D1851; Sicherheitsklasse: -
 | H2 Ebene 0 | WA-DL | 1105Wa 0811557436 | yes |  | m³ | Zimmer- und Holzbauarbeiten | Wand | Außenwand 7-Schalig | WA-DL |  |  | 0 |  | NEW |  |  | 0 | AllplanAttributes - Ortscode_Geschoßbezeichnung: E00; Sicherheitsklasse: -
 | H2 Ebene 0 | WA-TP | 1105Wa 0811557435 | yes |  | m² | Zimmer- und Holzbauarbeiten | Wand | Außenwand 7-Schalig | WA-TP |  |  | 0 |  | NEW |  |  | 0 | AllplanAttributes - Ortscode_Geschoßbezeichnung: E00; Sicherheitsklasse: -
 | H2 Ebene 0 | WA-KL | 1105Wa 0811557434 | yes |  | m² | Zimmer- und Holzbauarbeiten | Wand | Außenwand 7-Schalig | WA-KL |  |  | 0 |  | NEW |  |  | 0 | AllplanAttributes - Ortscode_Geschoßbezeichnung: E00; Sicherheitsklasse: -
 | H2 Ebene 0 | WA-TL | 1105Wa 0811557433 | yes |  | m² | Zimmer- und Holzbauarbeiten | Wand | Außenwand 7-Schalig | WA-TL |  |  | 0 |  | NEW |  |  | 0 | AllplanAttributes - Ortscode_Geschoßbezeichnung: E00; Sicherheitsklasse: -
 | H2 Ebene 0 | WA-HS | 1105Wa 0811557432 | yes |  | m² | Zimmer- und Holzbauarbeiten | Wand | Außenwand 7-Schalig | WA-HS |  |  | 0 |  | NEW |  |  | 0 | AllplanAttributes - Ortscode_Geschoßbezeichnung: E00; Sicherheitsklasse: -
 | H2 Ebene 0 | WA-LB | 1105Wa 0000000706 | yes |  | m² | Trockenbauarbeiten | Wand | Außenwand 7-Schalig | WA-LB |  |  | 0 |  | NEW |  |  | 0 | AllplanAttributes - Ortscode_Geschoßbezeichnung: E00; Sicherheitsklasse: -
 | H2 Ebene 0 | WA-HD | 1105Wa 0000000710 | yes |  | m³ | Zimmer- und Holzbauarbeiten | Wand | Außenwand 7-Schalig | WA-HD |  |  | 0 |  | NEW |  |  | 0 | AllplanAttributes - Ortscode_Geschoßbezeichnung: E00; Sicherheitsklasse: -
 | H2 Ebene 0 | WA-DL | 1105Wa 0000000730 | yes |  | m³ | Zimmer- und Holzbauarbeiten | Wand | Außenwand 7-Schalig | WA-DL |  |  | 0 |  | NEW |  |  | 0 | AllplanAttributes - Ortscode_Geschoßbezeichnung: E00; Sicherheitsklasse: -
 | H2 Ebene 0 | WA-TP | 1105Wa 0000000726 | yes |  | m² | Zimmer- und Holzbauarbeiten | Wand | Außenwand 7-Schalig | WA-TP |  |  | 0 |  | NEW |  |  | 0 | AllplanAttributes - Ortscode_Geschoßbezeichnung: E00; Sicherheitsklasse: -
 | H2 Ebene 0 | WA-KL | 1105Wa 0000000722 | yes |  | m² | Zimmer- und Holzbauarbeiten | Wand | Außenwand 7-Schalig | WA-KL |  |  | 0 |  | NEW |  |  | 0 | AllplanAttributes - Ortscode_Geschoßbezeichnung: E00; Sicherheitsklasse: -
 | H2 Ebene 0 | WA-TL | 1105Wa 0000000718 | yes |  | m² | Zimmer- und Holzbauarbeiten | Wand | Außenwand 7-Schalig | WA-TL |  |  | 0 |  | NEW |  |  | 0 | AllplanAttributes - Ortscode_Geschoßbezeichnung: E00; Sicherheitsklasse: -
 | H2 Ebene 0 | WA-HS | 1105Wa 0000000714 | yes |  | m² | Zimmer- und Holzbauarbeiten | Wand | Außenwand 7-Schalig | WA-HS |  |  | 0 |  | NEW |  |  | 0 | AllplanAttributes - Ortscode_Geschoßbezeichnung: E00; Sicherheitsklasse: -
 | H2 Ebene 0 | WA-LB | 1105Wa 0000000692 | yes |  | m² | Trockenbauarbeiten | Wand | Außenwand 7-Schalig | WA-LB |  |  | 0 |  | NEW |  |  | 0 | AllplanAttributes - Ortscode_Geschoßbezeichnung: E00; Sicherheitsklasse: -
 | H2 Ebene 0 | WA-HD | 1105Wa 0000000732 | yes |  | m³ | Zimmer- und Holzbauarbeiten | Wand | Außenwand 7-Schalig | WA-HD |  |  | 0 |  | NEW |  |  | 0 | AllplanAttributes - Ortscode_Geschoßbezeichnung: E00; Sicherheitsklasse: -
 | H2 Ebene 0 | WA-DL | 1105Wa 0000000734 | yes |  | m³ | Zimmer- und Holzbauarbeiten | Wand | Außenwand 7-Schalig | WA-DL |  |  | 0 |  | NEW |  |  | 0 | AllplanAttributes - Ortscode_Geschoßbezeichnung: E00; Sicherheitsklasse: -
 | H2 Ebene 0 | WA-TP | 1105Wa 0000000686 | yes |  | m² | Zimmer- und Holzbauarbeiten | Wand | Außenwand 7-Schalig | WA-TP |  |  | 0 |  | NEW |  |  | 0 | AllplanAttributes - Ortscode_Geschoßbezeichnung: E00; Sicherheitsklasse: -
 | H2 Ebene 0 | WA-KL | 1105Wa 0000000684 | yes |  | m² | Zimmer- und Holzbauarbeiten | Wand | Außenwand 7-Schalig | WA-KL |  |  | 0 |  | NEW |  |  | 0 | AllplanAttributes - Ortscode_Geschoßbezeichnung: E00; Sicherheitsklasse: -
 | H2 Ebene 0 | WA-TL | 1105Wa 0000000682 | yes |  | m² | Zimmer- und Holzbauarbeiten | Wand | Außenwand 7-Schalig | WA-TL |  |  | 0 |  | NEW |  |  | 0 | AllplanAttributes - Ortscode_Geschoßbezeichnung: E00; Sicherheitsklasse: -
 | H2 Ebene 0 | WA-HS | 1105Wa 0000000680 | yes |  | m² | Zimmer- und Holzbauarbeiten | Wand | Außenwand 7-Schalig | WA-HS |  |  | 0 |  | NEW |  |  | 0 | AllplanAttributes - Ortscode_Geschoßbezeichnung: E00; Sicherheitsklasse: -
 | H2 Ebene 0 | WA-LB | 1105Wa 0000000694 | yes |  | m² | Trockenbauarbeiten | Wand | Außenwand 7-Schalig | WA-LB |  |  | 0 |  | NEW |  |  | 0 | AllplanAttributes - Ortscode_Geschoßbezeichnung: E00; Sicherheitsklasse: -
 | H2 Ebene 0 | WA-HD | 1105Wa 0000000766 | yes |  | m³ | Zimmer- und Holzbauarbeiten | Wand | Außenwand 7-Schalig | WA-HD |  |  | 0 |  | NEW |  |  | 0 | AllplanAttributes - Ortscode_Geschoßbezeichnung: E00; Sicherheitsklasse: -
 | H2 Ebene 0 | WA-DL | 1105Wa 0000000764 | yes |  | m³ | Zimmer- und Holzbauarbeiten | Wand | Außenwand 7-Schalig | WA-DL |  |  | 0 |  | NEW |  |  | 0 | AllplanAttributes - Ortscode_Geschoßbezeichnung: E00; Sicherheitsklasse: -
 | H2 Ebene 0 | WA-TP | 1105Wa 0000000696 | yes |  | m² | Zimmer- und Holzbauarbeiten | Wand | Außenwand 7-Schalig | WA-TP |  |  | 0 |  | NEW |  |  | 0 | AllplanAttributes - Ortscode_Geschoßbezeichnung: E00; Sicherheitsklasse: -
 | H2 Ebene 0 | WA-KL | 1105Wa 0000000698 | yes |  | m² | Zimmer- und Holzbauarbeiten | Wand | Außenwand 7-Schalig | WA-KL |  |  | 0 |  | NEW |  |  | 0 | AllplanAttributes - Ortscode_Geschoßbezeichnung: E00; Sicherheitsklasse: -
 | H2 Ebene 0 | WA-TL | 1105Wa 0000000700 | yes |  | m² | Zimmer- und Holzbauarbeiten | Wand | Außenwand 7-Schalig | WA-TL |  |  | 0 |  | NEW |  |  | 0 | AllplanAttributes - Ortscode_Geschoßbezeichnung: E00; Sicherheitsklasse: -
 | H2 Ebene 0 | WA-HS | 1105Wa 0000000702 | yes |  | m² | Zimmer- und Holzbauarbeiten | Wand | Außenwand 7-Schalig | WA-HS |  |  | 0 |  | NEW |  |  | 0 | AllplanAttributes - Ortscode_Geschoßbezeichnung: E00; Sicherheitsklasse: -
 | H2 Ebene 0 | WA-LB | 1105Wa 0000000762 | yes |  | m² | Trockenbauarbeiten | Wand | Außenwand 7-Schalig | WA-LB |  |  | 0 |  | NEW |  |  | 0 | AllplanAttributes - Ortscode_Geschoßbezeichnung: E00; Sicherheitsklasse: -
 | H2 Ebene 0 | WA-HD | 1105Wa 0000000758 | yes |  | m³ | Zimmer- und Holzbauarbeiten | Wand | Außenwand 7-Schalig | WA-HD |  |  | 0 |  | NEW |  |  | 0 | AllplanAttributes - Ortscode_Geschoßbezeichnung: E00; Sicherheitsklasse: -
 | H2 Ebene 0 | WA-DL | 1105Wa 0000000738 | yes |  | m³ | Zimmer- und Holzbauarbeiten | Wand | Außenwand 7-Schalig | WA-DL |  |  | 0 |  | NEW |  |  | 0 | AllplanAttributes - Ortscode_Geschoßbezeichnung: E00; Sicherheitsklasse: -
 | H2 Ebene 0 | WA-TP | 1105Wa 0000000742 | yes |  | m² | Zimmer- und Holzbauarbeiten | Wand | Außenwand 7-Schalig | WA-TP |  |  | 0 |  | NEW |  |  | 0 | AllplanAttributes - Ortscode_Geschoßbezeichnung: E00; Sicherheitsklasse: -
 | H2 Ebene 0 | WA-KL | 1105Wa 0000000746 | yes |  | m² | Zimmer- und Holzbauarbeiten | Wand | Außenwand 7-Schalig | WA-KL |  |  | 0 |  | NEW |  |  | 0 | AllplanAttributes - Ortscode_Geschoßbezeichnung: E00; Sicherheitsklasse: -
 | H2 Ebene 0 | WA-TL | 1105Wa 0000000750 | yes |  | m² | Zimmer- und Holzbauarbeiten | Wand | Außenwand 7-Schalig | WA-TL |  |  | 0 |  | NEW |  |  | 0 | AllplanAttributes - Ortscode_Geschoßbezeichnung: E00; Sicherheitsklasse: -
 | H2 Ebene 0 | WA-HS | 1105Wa 0000000754 | yes |  | m² | Zimmer- und Holzbauarbeiten | Wand | Außenwand 7-Schalig | WA-HS |  |  | 0 |  | NEW |  |  | 0 | AllplanAttributes - Ortscode_Geschoßbezeichnung: E00; Sicherheitsklasse: -
 | H2 Ebene 0 | WA-LB | 1105Wa 0000001941 | yes |  | m² | Trockenbauarbeiten | Wand | Außenwand 7-Schalig | WA-LB |  |  | 0 |  | NEW |  |  | 0 | AllplanAttributes - Ortscode_Geschoßbezeichnung: E00; Sicherheitsklasse: -
 | H2 Ebene 0 | WA-HD | 1105Wa 0000001943 | yes |  | m³ | Zimmer- und Holzbauarbeiten | Wand | Außenwand 7-Schalig | WA-HD |  |  | 0 |  | NEW |  |  | 0 | AllplanAttributes - Ortscode_Geschoßbezeichnung: E00; Sicherheitsklasse: -
 | H2 Ebene 0 | WA-DL | 1105Wa 0000001945 | yes |  | m³ | Zimmer- und Holzbauarbeiten | Wand | Außenwand 7-Schalig | WA-DL |  |  | 0 |  | NEW |  |  | 0 | AllplanAttributes - Ortscode_Geschoßbezeichnung: E00; Sicherheitsklasse: -
 | H2 Ebene 0 | WA-TP | 1105Wa 0000001947 | yes |  | m² | Zimmer- und Holzbauarbeiten | Wand | Außenwand 7-Schalig | WA-TP |  |  | 0 |  | NEW |  |  | 0 | AllplanAttributes - Ortscode_Geschoßbezeichnung: E00; Sicherheitsklasse: -
 | H2 Ebene 0 | WA-KL | 1105Wa 0000001949 | yes |  | m² | Zimmer- und Holzbauarbeiten | Wand | Außenwand 7-Schalig | WA-KL |  |  | 0 |  | NEW |  |  | 0 | AllplanAttributes - Ortscode_Geschoßbezeichnung: E00; Sicherheitsklasse: -
 | H2 Ebene 0 | WA-TL | 1105Wa 0000001951 | yes |  | m² | Zimmer- und Holzbauarbeiten | Wand | Außenwand 7-Schalig | WA-TL |  |  | 0 |  | NEW |  |  | 0 | AllplanAttributes - Ortscode_Geschoßbezeichnung: E00; Sicherheitsklasse: -
 | H2 Ebene 0 | WA-HS | 1105Wa 0000001953 | yes |  | m² | Zimmer- und Holzbauarbeiten | Wand | Außenwand 7-Schalig | WA-HS |  |  | 0 |  | NEW |  |  | 0 | AllplanAttributes - Ortscode_Geschoßbezeichnung: E00; Sicherheitsklasse: -
 | H2 Ebene 0 | WA-LB | 1105Wa 0000002517 | yes |  | m² | Trockenbauarbeiten | Wand | Außenwand 7-Schalig | WA-LB |  |  | 0 |  | NEW |  |  | 0 | AllplanAttributes - Ortscode_Geschoßbezeichnung: E00; Sicherheitsklasse: -
 | H2 Ebene 0 | WA-HD | 1105Wa 0000002519 | yes |  | m³ | Zimmer- und Holzbauarbeiten | Wand | Außenwand 7-Schalig | WA-HD |  |  | 0 |  | NEW |  |  | 0 | AllplanAttributes - Ortscode_Geschoßbezeichnung: E00; Sicherheitsklasse: -
 | H2 Ebene 0 | WA-DL | 1105Wa 0000002521 | yes |  | m³ | Zimmer- und Holzbauarbeiten | Wand | Außenwand 7-Schalig | WA-DL |  |  | 0 |  | NEW |  |  | 0 | AllplanAttributes - Ortscode_Geschoßbezeichnung: E00; Sicherheitsklasse: -
 | H2 Ebene 0 | WA-TP | 1105Wa 0000002523 | yes |  | m² | Zimmer- und Holzbauarbeiten | Wand | Außenwand 7-Schalig | WA-TP |  |  | 0 |  | NEW |  |  | 0 | AllplanAttributes - Ortscode_Geschoßbezeichnung: E00; Sicherheitsklasse: -
 | H2 Ebene 0 | WA-KL | 1105Wa 0000002525 | yes |  | m² | Zimmer- und Holzbauarbeiten | Wand | Außenwand 7-Schalig | WA-KL |  |  | 0 |  | NEW |  |  | 0 | AllplanAttributes - Ortscode_Geschoßbezeichnung: E00; Sicherheitsklasse: -
 | H2 Ebene 0 | WA-TL | 1105Wa 0000002527 | yes |  | m² | Zimmer- und Holzbauarbeiten | Wand | Außenwand 7-Schalig | WA-TL |  |  | 0 |  | NEW |  |  | 0 | AllplanAttributes - Ortscode_Geschoßbezeichnung: E00; Sicherheitsklasse: -
 | H2 Ebene 0 | WA-HS | 1105Wa 0000002529 | yes |  | m² | Zimmer- und Holzbauarbeiten | Wand | Außenwand 7-Schalig | WA-HS |  |  | 0 |  | NEW |  |  | 0 | AllplanAttributes - Ortscode_Geschoßbezeichnung: E00; Sicherheitsklasse: -
 | H2 Ebene 0 | WA-LB | 1105Wa 0000000962 | yes |  | m² | Trockenbauarbeiten | Wand | Außenwand 7-Schalig | WA-LB |  |  | 0 |  | NEW |  |  | 0 | AllplanAttributes - Ortscode_Geschoßbezeichnung: E00; Sicherheitsklasse: -
 | H2 Ebene 0 | WA-HD | 1105Wa 0000000958 | yes |  | m³ | Zimmer- und Holzbauarbeiten | Wand | Außenwand 7-Schalig | WA-HD |  |  | 0 |  | NEW |  |  | 0 | AllplanAttributes - Ortscode_Geschoßbezeichnung: E00; Sicherheitsklasse: -
 | H2 Ebene 0 | WA-DL | 1105Wa 0000000938 | yes |  | m³ | Zimmer- und Holzbauarbeiten | Wand | Außenwand 7-Schalig | WA-DL |  |  | 0 |  | NEW |  |  | 0 | AllplanAttributes - Ortscode_Geschoßbezeichnung: E00; Sicherheitsklasse: -
 | H2 Ebene 0 | WA-TP | 1105Wa 0000000942 | yes |  | m² | Zimmer- und Holzbauarbeiten | Wand | Außenwand 7-Schalig | WA-TP |  |  | 0 |  | NEW |  |  | 0 | AllplanAttributes - Ortscode_Geschoßbezeichnung: E00; Sicherheitsklasse: -
 | H2 Ebene 0 | WA-KL | 1105Wa 0000000946 | yes |  | m² | Zimmer- und Holzbauarbeiten | Wand | Außenwand 7-Schalig | WA-KL |  |  | 0 |  | NEW |  |  | 0 | AllplanAttributes - Ortscode_Geschoßbezeichnung: E00; Sicherheitsklasse: -
 | H2 Ebene 0 | WA-TL | 1105Wa 0000000950 | yes |  | m² | Zimmer- und Holzbauarbeiten | Wand | Außenwand 7-Schalig | WA-TL |  |  | 0 |  | NEW |  |  | 0 | AllplanAttributes - Ortscode_Geschoßbezeichnung: E00; Sicherheitsklasse: -
 | H2 Ebene 0 | WA-HS | 1105Wa 0000000954 | yes |  | m² | Zimmer- und Holzbauarbeiten | Wand | Außenwand 7-Schalig | WA-HS |  |  | 0 |  | NEW |  |  | 0 | AllplanAttributes - Ortscode_Geschoßbezeichnung: E00; Sicherheitsklasse: -
 | H2 Ebene 0 | WA-LB | 1105Wa 0000000898 | yes |  | m² | Trockenbauarbeiten | Wand | Außenwand 7-Schalig | WA-LB |  |  | 0 |  | NEW |  |  | 0 | AllplanAttributes - Ortscode_Geschoßbezeichnung: E00; Sicherheitsklasse: -
 | H2 Ebene 0 | WA-HD | 1105Wa 0000000966 | yes |  | m³ | Zimmer- und Holzbauarbeiten | Wand | Außenwand 7-Schalig | WA-HD |  |  | 0 |  | NEW |  |  | 0 | AllplanAttributes - Ortscode_Geschoßbezeichnung: E00; Sicherheitsklasse: -
 | H2 Ebene 0 | WA-DL | 1105Wa 0000000964 | yes |  | m³ | Zimmer- und Holzbauarbeiten | Wand | Außenwand 7-Schalig | WA-DL |  |  | 0 |  | NEW |  |  | 0 | AllplanAttributes - Ortscode_Geschoßbezeichnung: E00; Sicherheitsklasse: -
 | H2 Ebene 0 | WA-TP | 1105Wa 0000000900 | yes |  | m² | Zimmer- und Holzbauarbeiten | Wand | Außenwand 7-Schalig | WA-TP |  |  | 0 |  | NEW |  |  | 0 | AllplanAttributes - Ortscode_Geschoßbezeichnung: E00; Sicherheitsklasse: -
 | H2 Ebene 0 | WA-KL | 1105Wa 0000000902 | yes |  | m² | Zimmer- und Holzbauarbeiten | Wand | Außenwand 7-Schalig | WA-KL |  |  | 0 |  | NEW |  |  | 0 | AllplanAttributes - Ortscode_Geschoßbezeichnung: E00; Sicherheitsklasse: -
 | H2 Ebene 0 | WA-TL | 1105Wa 0000000904 | yes |  | m² | Zimmer- und Holzbauarbeiten | Wand | Außenwand 7-Schalig | WA-TL |  |  | 0 |  | NEW |  |  | 0 | AllplanAttributes - Ortscode_Geschoßbezeichnung: E00; Sicherheitsklasse: -
 | H2 Ebene 0 | WA-HS | 1105Wa 0000000906 | yes |  | m² | Zimmer- und Holzbauarbeiten | Wand | Außenwand 7-Schalig | WA-HS |  |  | 0 |  | NEW |  |  | 0 | AllplanAttributes - Ortscode_Geschoßbezeichnung: E00; Sicherheitsklasse: -
 | H2 Ebene 0 | WA-LB | 1105Wa 0000000910 | yes |  | m² | Trockenbauarbeiten | Wand | Außenwand 7-Schalig | WA-LB |  |  | 0 |  | NEW |  |  | 0 | AllplanAttributes - Ortscode_Geschoßbezeichnung: E00; Sicherheitsklasse: -
 | H2 Ebene 0 | WA-HD | 1105Wa 0000000914 | yes |  | m³ | Zimmer- und Holzbauarbeiten | Wand | Außenwand 7-Schalig | WA-HD |  |  | 0 |  | NEW |  |  | 0 | AllplanAttributes - Ortscode_Geschoßbezeichnung: E00; Sicherheitsklasse: -
 | H2 Ebene 0 | WA-DL | 1105Wa 0000000934 | yes |  | m³ | Zimmer- und Holzbauarbeiten | Wand | Außenwand 7-Schalig | WA-DL |  |  | 0 |  | NEW |  |  | 0 | AllplanAttributes - Ortscode_Geschoßbezeichnung: E00; Sicherheitsklasse: -
 | H2 Ebene 0 | WA-TP | 1105Wa 0000000930 | yes |  | m² | Zimmer- und Holzbauarbeiten | Wand | Außenwand 7-Schalig | WA-TP |  |  | 0 |  | NEW |  |  | 0 | AllplanAttributes - Ortscode_Geschoßbezeichnung: E00; Sicherheitsklasse: -
 | H2 Ebene 0 | WA-KL | 1105Wa 0000000926 | yes |  | m² | Zimmer- und Holzbauarbeiten | Wand | Außenwand 7-Schalig | WA-KL |  |  | 0 |  | NEW |  |  | 0 | AllplanAttributes - Ortscode_Geschoßbezeichnung: E00; Sicherheitsklasse: -
 | H2 Ebene 0 | WA-TL | 1105Wa 0000000922 | yes |  | m² | Zimmer- und Holzbauarbeiten | Wand | Außenwand 7-Schalig | WA-TL |  |  | 0 |  | NEW |  |  | 0 | AllplanAttributes - Ortscode_Geschoßbezeichnung: E00; Sicherheitsklasse: -
 | H2 Ebene 0 | WA-HS | 1105Wa 0000000918 | yes |  | m² | Zimmer- und Holzbauarbeiten | Wand | Außenwand 7-Schalig | WA-HS |  |  | 0 |  | NEW |  |  | 0 | AllplanAttributes - Ortscode_Geschoßbezeichnung: E00; Sicherheitsklasse: -
 | H2 Ebene 0 | WA-LB | 1105Wa 0000002831 | yes |  | m² | Trockenbauarbeiten | Wand | Außenwand 7-Schalig | WA-LB |  |  | 0 |  | NEW |  |  | 0 | AllplanAttributes - Ortscode_Geschoßbezeichnung: E00; Sicherheitsklasse: -
 | H2 Ebene 0 | WA-HD | 1105Wa 0000002833 | yes |  | m³ | Zimmer- und Holzbauarbeiten | Wand | Außenwand 7-Schalig | WA-HD |  |  | 0 |  | NEW |  |  | 0 | AllplanAttributes - Ortscode_Geschoßbezeichnung: E00; Sicherheitsklasse: -
 | H2 Ebene 0 | WA-DL | 1105Wa 0000002835 | yes |  | m³ | Zimmer- und Holzbauarbeiten | Wand | Außenwand 7-Schalig | WA-DL |  |  | 0 |  | NEW |  |  | 0 | AllplanAttributes - Ortscode_Geschoßbezeichnung: E00; Sicherheitsklasse: -
 | H2 Ebene 0 | WA-TP | 1105Wa 0000002829 | yes |  | m² | Zimmer- und Holzbauarbeiten | Wand | Außenwand 7-Schalig | WA-TP |  |  | 0 |  | NEW |  |  | 0 | AllplanAttributes - Ortscode_Geschoßbezeichnung: E00; Sicherheitsklasse: -
 | H2 Ebene 0 | WA-KL | 1105Wa 0000002827 | yes |  | m² | Zimmer- und Holzbauarbeiten | Wand | Außenwand 7-Schalig | WA-KL |  |  | 0 |  | NEW |  |  | 0 | AllplanAttributes - Ortscode_Geschoßbezeichnung: E00; Sicherheitsklasse: -
 | H2 Ebene 0 | WA-TL | 1105Wa 0000002825 | yes |  | m² | Zimmer- und Holzbauarbeiten | Wand | Außenwand 7-Schalig | WA-TL |  |  | 0 |  | NEW |  |  | 0 | AllplanAttributes - Ortscode_Geschoßbezeichnung: E00; Sicherheitsklasse: -
 | H2 Ebene 0 | WA-HS | 1105Wa 0000002823 | yes |  | m² | Zimmer- und Holzbauarbeiten | Wand | Außenwand 7-Schalig | WA-HS |  |  | 0 |  | NEW |  |  | 0 | AllplanAttributes - Ortscode_Geschoßbezeichnung: E00; Sicherheitsklasse: -
 | H2 Ebene 0 | WA-LB | 1105Wa 0000002877 | yes |  | m² | Trockenbauarbeiten | Wand | Außenwand 7-Schalig | WA-LB |  |  | 0 |  | NEW |  |  | 0 | AllplanAttributes - Ortscode_Geschoßbezeichnung: E00; Sicherheitsklasse: -
 | H2 Ebene 0 | WA-HD | 1105Wa 0000002875 | yes |  | m³ | Zimmer- und Holzbauarbeiten | Wand | Außenwand 7-Schalig | WA-HD |  |  | 0 |  | NEW |  |  | 0 | AllplanAttributes - Ortscode_Geschoßbezeichnung: E00; Sicherheitsklasse: -
 | H2 Ebene 0 | WA-DL | 1105Wa 0000002873 | yes |  | m³ | Zimmer- und Holzbauarbeiten | Wand | Außenwand 7-Schalig | WA-DL |  |  | 0 |  | NEW |  |  | 0 | AllplanAttributes - Ortscode_Geschoßbezeichnung: E00; Sicherheitsklasse: -
 | H2 Ebene 0 | WA-TP | 1105Wa 0000002871 | yes |  | m² | Zimmer- und Holzbauarbeiten | Wand | Außenwand 7-Schalig | WA-TP |  |  | 0 |  | NEW |  |  | 0 | AllplanAttributes - Ortscode_Geschoßbezeichnung: E00; Sicherheitsklasse: -
 | H2 Ebene 0 | WA-KL | 1105Wa 0000002869 | yes |  | m² | Zimmer- und Holzbauarbeiten | Wand | Außenwand 7-Schalig | WA-KL |  |  | 0 |  | NEW |  |  | 0 | AllplanAttributes - Ortscode_Geschoßbezeichnung: E00; Sicherheitsklasse: -
 | H2 Ebene 0 | WA-TL | 1105Wa 0000002867 | yes |  | m² | Zimmer- und Holzbauarbeiten | Wand | Außenwand 7-Schalig | WA-TL |  |  | 0 |  | NEW |  |  | 0 | AllplanAttributes - Ortscode_Geschoßbezeichnung: E00; Sicherheitsklasse: -
 | H2 Ebene 0 | WA-HS | 1105Wa 0000002865 | yes |  | m² | Zimmer- und Holzbauarbeiten | Wand | Außenwand 7-Schalig | WA-HS |  |  | 0 |  | NEW |  |  | 0 | AllplanAttributes - Ortscode_Geschoßbezeichnung: E00; Sicherheitsklasse: -
 | H2 Ebene 0 | WA-LB | 1105Wa 0000002911 | yes |  | m² | Trockenbauarbeiten | Wand | Außenwand 7-Schalig | WA-LB |  |  | 0 |  | NEW |  |  | 0 | AllplanAttributes - Ortscode_Geschoßbezeichnung: E00; Sicherheitsklasse: -
 | H2 Ebene 0 | WA-HD | 1105Wa 0000002913 | yes |  | m³ | Zimmer- und Holzbauarbeiten | Wand | Außenwand 7-Schalig | WA-HD |  |  | 0 |  | NEW |  |  | 0 | AllplanAttributes - Ortscode_Geschoßbezeichnung: E00; Sicherheitsklasse: -
 | H2 Ebene 0 | WA-DL | 1105Wa 0000002915 | yes |  | m³ | Zimmer- und Holzbauarbeiten | Wand | Außenwand 7-Schalig | WA-DL |  |  | 0 |  | NEW |  |  | 0 | AllplanAttributes - Ortscode_Geschoßbezeichnung: E00; Sicherheitsklasse: -
 | H2 Ebene 0 | WA-TP | 1105Wa 0000002917 | yes |  | m² | Zimmer- und Holzbauarbeiten | Wand | Außenwand 7-Schalig | WA-TP |  |  | 0 |  | NEW |  |  | 0 | AllplanAttributes - Ortscode_Geschoßbezeichnung: E00; Sicherheitsklasse: -
 | H2 Ebene 0 | WA-KL | 1105Wa 0000002919 | yes |  | m² | Zimmer- und Holzbauarbeiten | Wand | Außenwand 7-Schalig | WA-KL |  |  | 0 |  | NEW |  |  | 0 | AllplanAttributes - Ortscode_Geschoßbezeichnung: E00; Sicherheitsklasse: -
 | H2 Ebene 0 | WA-TL | 1105Wa 0000002921 | yes |  | m² | Zimmer- und Holzbauarbeiten | Wand | Außenwand 7-Schalig | WA-TL |  |  | 0 |  | NEW |  |  | 0 | AllplanAttributes - Ortscode_Geschoßbezeichnung: E00; Sicherheitsklasse: -
 | H2 Ebene 0 | WA-HS | 1105Wa 0000002923 | yes |  | m² | Zimmer- und Holzbauarbeiten | Wand | Außenwand 7-Schalig | WA-HS |  |  | 0 |  | NEW |  |  | 0 | AllplanAttributes - Ortscode_Geschoßbezeichnung: E00; Sicherheitsklasse: -
 | H2 Ebene 0 | WA-LB | 1105Wa 0000002926 | yes |  | m² | Trockenbauarbeiten | Wand | Außenwand 7-Schalig | WA-LB |  |  | 0 |  | NEW |  |  | 0 | AllplanAttributes - Ortscode_Geschoßbezeichnung: E00; Sicherheitsklasse: -
 | H2 Ebene 0 | WA-HD | 1105Wa 0000002928 | yes |  | m³ | Zimmer- und Holzbauarbeiten | Wand | Außenwand 7-Schalig | WA-HD |  |  | 0 |  | NEW |  |  | 0 | AllplanAttributes - Ortscode_Geschoßbezeichnung: E00; Sicherheitsklasse: -
 | H2 Ebene 0 | WA-DL | 1105Wa 0000002939 | yes |  | m³ | Zimmer- und Holzbauarbeiten | Wand | Außenwand 7-Schalig | WA-DL |  |  | 0 |  | NEW |  |  | 0 | AllplanAttributes - Ortscode_Geschoßbezeichnung: E00; Sicherheitsklasse: -
 | H2 Ebene 0 | WA-TP | 1105Wa 0000002937 | yes |  | m² | Zimmer- und Holzbauarbeiten | Wand | Außenwand 7-Schalig | WA-TP |  |  | 0 |  | NEW |  |  | 0 | AllplanAttributes - Ortscode_Geschoßbezeichnung: E00; Sicherheitsklasse: -
 | H2 Ebene 0 | WA-KL | 1105Wa 0000002935 | yes |  | m² | Zimmer- und Holzbauarbeiten | Wand | Außenwand 7-Schalig | WA-KL |  |  | 0 |  | NEW |  |  | 0 | AllplanAttributes - Ortscode_Geschoßbezeichnung: E00; Sicherheitsklasse: -
 | H2 Ebene 0 | WA-TL | 1105Wa 0000002933 | yes |  | m² | Zimmer- und Holzbauarbeiten | Wand | Außenwand 7-Schalig | WA-TL |  |  | 0 |  | NEW |  |  | 0 | AllplanAttributes - Ortscode_Geschoßbezeichnung: E00; Sicherheitsklasse: -
 | H2 Ebene 0 | WA-HS | 1105Wa 0000002931 | yes |  | m² | Zimmer- und Holzbauarbeiten | Wand | Außenwand 7-Schalig | WA-HS |  |  | 0 |  | NEW |  |  | 0 | AllplanAttributes - Ortscode_Geschoßbezeichnung: E00; Sicherheitsklasse: -
 | H2 Ebene 0 | WA-LB | 1105Wa 0000003057 | yes |  | m² | Trockenbauarbeiten | Wand | Außenwand 7-Schalig | WA-LB |  |  | 0 |  | NEW |  |  | 0 | AllplanAttributes - Ortscode_Geschoßbezeichnung: E00; Sicherheitsklasse: -
 | H2 Ebene 0 | WA-HD | 1105Wa 0000003053 | yes |  | m³ | Zimmer- und Holzbauarbeiten | Wand | Außenwand 7-Schalig | WA-HD |  |  | 0 |  | NEW |  |  | 0 | AllplanAttributes - Ortscode_Geschoßbezeichnung: E00; Sicherheitsklasse: -
 | H2 Ebene 0 | WA-DL | 1105Wa 0000003049 | yes |  | m³ | Zimmer- und Holzbauarbeiten | Wand | Außenwand 7-Schalig | WA-DL |  |  | 0 |  | NEW |  |  | 0 | AllplanAttributes - Ortscode_Geschoßbezeichnung: E00; Sicherheitsklasse: -
 | H2 Ebene 0 | WA-TP | 1105Wa 0000003045 | yes |  | m² | Zimmer- und Holzbauarbeiten | Wand | Außenwand 7-Schalig | WA-TP |  |  | 0 |  | NEW |  |  | 0 | AllplanAttributes - Ortscode_Geschoßbezeichnung: E00; Sicherheitsklasse: -
 | H2 Ebene 0 | WA-KL | 1105Wa 0000003041 | yes |  | m² | Zimmer- und Holzbauarbeiten | Wand | Außenwand 7-Schalig | WA-KL |  |  | 0 |  | NEW |  |  | 0 | AllplanAttributes - Ortscode_Geschoßbezeichnung: E00; Sicherheitsklasse: -
 | H2 Ebene 0 | WA-TL | 1105Wa 0000003037 | yes |  | m² | Zimmer- und Holzbauarbeiten | Wand | Außenwand 7-Schalig | WA-TL |  |  | 0 |  | NEW |  |  | 0 | AllplanAttributes - Ortscode_Geschoßbezeichnung: E00; Sicherheitsklasse: -
 | H2 Ebene 0 | WA-HS | 1105Wa 0000003033 | yes |  | m² | Zimmer- und Holzbauarbeiten | Wand | Außenwand 7-Schalig | WA-HS |  |  | 0 |  | NEW |  |  | 0 | AllplanAttributes - Ortscode_Geschoßbezeichnung: E00; Sicherheitsklasse: -
 | H2 Ebene 0 | WA-LB | 1105Wa 0000003128 | yes |  | m² | Trockenbauarbeiten | Wand | Außenwand 7-Schalig | WA-LB |  |  | 0 |  | NEW |  |  | 0 | AllplanAttributes - Ortscode_Geschoßbezeichnung: E00; Sicherheitsklasse: -
 | H2 Ebene 0 | WA-HD | 1105Wa 0000003130 | yes |  | m³ | Zimmer- und Holzbauarbeiten | Wand | Außenwand 7-Schalig | WA-HD |  |  | 0 |  | NEW |  |  | 0 | AllplanAttributes - Ortscode_Geschoßbezeichnung: E00; Sicherheitsklasse: -
 | H2 Ebene 0 | WA-DL | 1105Wa 0000003132 | yes |  | m³ | Zimmer- und Holzbauarbeiten | Wand | Außenwand 7-Schalig | WA-DL |  |  | 0 |  | NEW |  |  | 0 | AllplanAttributes - Ortscode_Geschoßbezeichnung: E00; Sicherheitsklasse: -
 | H2 Ebene 0 | WA-TP | 1105Wa 0000003134 | yes |  | m² | Zimmer- und Holzbauarbeiten | Wand | Außenwand 7-Schalig | WA-TP |  |  | 0 |  | NEW |  |  | 0 | AllplanAttributes - Ortscode_Geschoßbezeichnung: E00; Sicherheitsklasse: -
 | H2 Ebene 0 | WA-KL | 1105Wa 0000003136 | yes |  | m² | Zimmer- und Holzbauarbeiten | Wand | Außenwand 7-Schalig | WA-KL |  |  | 0 |  | NEW |  |  | 0 | AllplanAttributes - Ortscode_Geschoßbezeichnung: E00; Sicherheitsklasse: -
 | H2 Ebene 0 | WA-TL | 1105Wa 0000003138 | yes |  | m² | Zimmer- und Holzbauarbeiten | Wand | Außenwand 7-Schalig | WA-TL |  |  | 0 |  | NEW |  |  | 0 | AllplanAttributes - Ortscode_Geschoßbezeichnung: E00; Sicherheitsklasse: -
 | H2 Ebene 0 | WA-HS | 1105Wa 0000003140 | yes |  | m² | Zimmer- und Holzbauarbeiten | Wand | Außenwand 7-Schalig | WA-HS |  |  | 0 |  | NEW |  |  | 0 | AllplanAttributes - Ortscode_Geschoßbezeichnung: E00; Sicherheitsklasse: -
 | H2 Ebene 0 | WA-LB | 1105Wa 0000003146 | yes |  | m² | Trockenbauarbeiten | Wand | Außenwand 7-Schalig | WA-LB |  |  | 0 |  | NEW |  |  | 0 | AllplanAttributes - Ortscode_Geschoßbezeichnung: E00; Sicherheitsklasse: -
 | H2 Ebene 0 | WA-HD | 1105Wa 0000003144 | yes |  | m³ | Zimmer- und Holzbauarbeiten | Wand | Außenwand 7-Schalig | WA-HD |  |  | 0 |  | NEW |  |  | 0 | AllplanAttributes - Ortscode_Geschoßbezeichnung: E00; Sicherheitsklasse: -
 | H2 Ebene 0 | WA-DL | 1105Wa 0000003142 | yes |  | m³ | Zimmer- und Holzbauarbeiten | Wand | Außenwand 7-Schalig | WA-DL |  |  | 0 |  | NEW |  |  | 0 | AllplanAttributes - Ortscode_Geschoßbezeichnung: E00; Sicherheitsklasse: -
 | H2 Ebene 0 | WA-TP | 1105Wa 0000003148 | yes |  | m² | Zimmer- und Holzbauarbeiten | Wand | Außenwand 7-Schalig | WA-TP |  |  | 0 |  | NEW |  |  | 0 | AllplanAttributes - Ortscode_Geschoßbezeichnung: E00; Sicherheitsklasse: -
 | H2 Ebene 0 | WA-KL | 1105Wa 0000003150 | yes |  | m² | Zimmer- und Holzbauarbeiten | Wand | Außenwand 7-Schalig | WA-KL |  |  | 0 |  | NEW |  |  | 0 | AllplanAttributes - Ortscode_Geschoßbezeichnung: E00; Sicherheitsklasse: -
 | H2 Ebene 0 | WA-TL | 1105Wa 0000003152 | yes |  | m² | Zimmer- und Holzbauarbeiten | Wand | Außenwand 7-Schalig | WA-TL |  |  | 0 |  | NEW |  |  | 0 | AllplanAttributes - Ortscode_Geschoßbezeichnung: E00; Sicherheitsklasse: -
 | H2 Ebene 0 | WA-HS | 1105Wa 0000003154 | yes |  | m² | Zimmer- und Holzbauarbeiten | Wand | Außenwand 7-Schalig | WA-HS |  |  | 0 |  | NEW |  |  | 0 | AllplanAttributes - Ortscode_Geschoßbezeichnung: E00; Sicherheitsklasse: -
 | H2 Ebene 0 | WA-LB | 1105Wa 0811632325 | yes |  | m² | Trockenbauarbeiten | Wand | Außenwand 7-Schalig | WA-LB |  |  | 0 |  | NEW |  |  | 0 | AllplanAttributes - Ortscode_Geschoßbezeichnung: E00; Sicherheitsklasse: -
 | H2 Ebene 0 | WA-HD | 1105Wa 0811632331 | yes |  | m³ | Zimmer- und Holzbauarbeiten | Wand | Außenwand 7-Schalig | WA-HD |  |  | 0 |  | NEW |  |  | 0 | AllplanAttributes - Ortscode_Geschoßbezeichnung: E00; Sicherheitsklasse: -
 | H2 Ebene 0 | WA-DL | 1105Wa 0811632330 | yes |  | m³ | Zimmer- und Holzbauarbeiten | Wand | Außenwand 7-Schalig | WA-DL |  |  | 0 |  | NEW |  |  | 0 | AllplanAttributes - Ortscode_Geschoßbezeichnung: E00; Sicherheitsklasse: -
 | H2 Ebene 0 | WA-LB | 1105Wa 0811632329 | yes |  | m² | Trockenbauarbeiten | Wand | Außenwand 7-Schalig | WA-LB |  |  | 0 |  | NEW |  |  | 0 | AllplanAttributes - Ortscode_Geschoßbezeichnung: E00; Sicherheitsklasse: -
 | H2 Ebene 0 | WA-KL | 1105Wa 0811632328 | yes |  | m² | Zimmer- und Holzbauarbeiten | Wand | Außenwand 7-Schalig | WA-KL |  |  | 0 |  | NEW |  |  | 0 | AllplanAttributes - Ortscode_Geschoßbezeichnung: E00; Sicherheitsklasse: -
 | H2 Ebene 0 | WA-TL | 1105Wa 0811632327 | yes |  | m² | Zimmer- und Holzbauarbeiten | Wand | Außenwand 7-Schalig | WA-TL |  |  | 0 |  | NEW |  |  | 0 | AllplanAttributes - Ortscode_Geschoßbezeichnung: E00; Sicherheitsklasse: -
 | H2 Ebene 0 | WA-HS | 1105Wa 0811632326 | yes |  | m² | Zimmer- und Holzbauarbeiten | Wand | Außenwand 7-Schalig | WA-HS |  |  | 0 |  | NEW |  |  | 0 | AllplanAttributes - Ortscode_Geschoßbezeichnung: E00; Sicherheitsklasse: -
 | H2 Ebene 0 | WA-LB | 1105Wa 0000001193 | yes |  | m² | Trockenbauarbeiten | Wand | Außenwand 7-Schalig | WA-LB |  |  | 0 |  |  |  |  | 0 | AllplanAttributes - Ortscode_Geschoßbezeichnung: E00; Sicherheitsklasse: -
 | H2 Ebene 0 | WA-HD | 1105Wa 0000001197 | yes |  | m³ | Zimmer- und Holzbauarbeiten | Wand | Außenwand 7-Schalig | WA-HD |  |  | 0 |  |  |  |  | 0 | AllplanAttributes - Ortscode_Geschoßbezeichnung: E00; ash D_Detailverweis: DT C; ash D_Plannummer: D1851; Sicherheitsklasse: -
 | H2 Ebene 0 | WA-DL | 1105Wa 0000001201 | yes |  | m³ | Zimmer- und Holzbauarbeiten | Wand | Außenwand 7-Schalig | WA-DL |  |  | 0 |  |  |  |  | 0 | AllplanAttributes - Ortscode_Geschoßbezeichnung: E00; Sicherheitsklasse: -
 | H2 Ebene 0 | WA-TP | 1105Wa 0000001205 | yes |  | m² | Zimmer- und Holzbauarbeiten | Wand | Außenwand 7-Schalig | WA-TP |  |  | 0 |  |  |  |  | 0 | AllplanAttributes - Ortscode_Geschoßbezeichnung: E00; Sicherheitsklasse: -
 | H2 Ebene 0 | WA-KL | 1105Wa 0000001209 | yes |  | m² | Zimmer- und Holzbauarbeiten | Wand | Außenwand 7-Schalig | WA-KL |  |  | 0 |  |  |  |  | 0 | AllplanAttributes - Ortscode_Geschoßbezeichnung: E00; Sicherheitsklasse: -
 | H2 Ebene 0 | WA-TL | 1105Wa 0000001213 | yes |  | m² | Zimmer- und Holzbauarbeiten | Wand | Außenwand 7-Schalig | WA-TL |  |  | 0 |  |  |  |  | 0 | AllplanAttributes - Ortscode_Geschoßbezeichnung: E00; Sicherheitsklasse: -
 | H2 Ebene 0 | WA-HS | 1105Wa 0000001217 | yes |  | m² | Zimmer- und Holzbauarbeiten | Wand | Außenwand 7-Schalig | WA-HS |  |  | 0 |  |  |  |  | 0 | AllplanAttributes - Ortscode_Geschoßbezeichnung: E00; Sicherheitsklasse: -
 | H2 Ebene 0 | WA-LB | 1105Wa 0000001093 | yes |  | m² | Trockenbauarbeiten | Wand | Außenwand 7-Schalig | WA-LB |  |  | 0 |  |  |  |  | 0 | AllplanAttributes - Ortscode_Geschoßbezeichnung: E00; Sicherheitsklasse: -
 | H2 Ebene 0 | WA-HD | 1105Wa 0000001097 | yes |  | m³ | Zimmer- und Holzbauarbeiten | Wand | Außenwand 7-Schalig | WA-HD |  |  | 0 |  |  |  |  | 0 | AllplanAttributes - Ortscode_Geschoßbezeichnung: E00; ash D_Detailverweis: FS 2; ash D_Plannummer: D781; Sicherheitsklasse: -
 | H2 Ebene 0 | WA-DL | 1105Wa 0000001117 | yes |  | m³ | Zimmer- und Holzbauarbeiten | Wand | Außenwand 7-Schalig | WA-DL |  |  | 0 |  |  |  |  | 0 | AllplanAttributes - Ortscode_Geschoßbezeichnung: E00; Sicherheitsklasse: -
 | H2 Ebene 0 | WA-TP | 1105Wa 0000001113 | yes |  | m² | Zimmer- und Holzbauarbeiten | Wand | Außenwand 7-Schalig | WA-TP |  |  | 0 |  |  |  |  | 0 | AllplanAttributes - Ortscode_Geschoßbezeichnung: E00; Sicherheitsklasse: -
 | H2 Ebene 0 | WA-KL | 1105Wa 0000001109 | yes |  | m² | Zimmer- und Holzbauarbeiten | Wand | Außenwand 7-Schalig | WA-KL |  |  | 0 |  |  |  |  | 0 | AllplanAttributes - Ortscode_Geschoßbezeichnung: E00; Sicherheitsklasse: -
 | H2 Ebene 0 | WA-TL | 1105Wa 0000001105 | yes |  | m² | Zimmer- und Holzbauarbeiten | Wand | Außenwand 7-Schalig | WA-TL |  |  | 0 |  |  |  |  | 0 | AllplanAttributes - Ortscode_Geschoßbezeichnung: E00; Sicherheitsklasse: -
 | H2 Ebene 0 | WA-HS | 1105Wa 0000001101 | yes |  | m² | Zimmer- und Holzbauarbeiten | Wand | Außenwand 7-Schalig | WA-HS |  |  | 0 |  |  |  |  | 0 | AllplanAttributes - Ortscode_Geschoßbezeichnung: E00; Sicherheitsklasse: -
 | H2 Ebene 0 | WA-LB | 1105Wa 0000003112 | yes |  | m² | Trockenbauarbeiten | Wand | Außenwand 7-Schalig | WA-LB |  |  | 0 |  | NEW |  |  | 0 | AllplanAttributes - Ortscode_Geschoßbezeichnung: E00; Sicherheitsklasse: -
 | H2 Ebene 0 | WA-HD | 1105Wa 0000003108 | yes |  | m³ | Zimmer- und Holzbauarbeiten | Wand | Außenwand 7-Schalig | WA-HD |  |  | 0 |  | NEW |  |  | 0 | AllplanAttributes - Ortscode_Geschoßbezeichnung: E00; ash D_Detailverweis: DT B; ash D_Plannummer: D1851; Sicherheitsklasse: -
 | H2 Ebene 0 | WA-DL | 1105Wa 0000003104 | yes |  | m³ | Zimmer- und Holzbauarbeiten | Wand | Außenwand 7-Schalig | WA-DL |  |  | 0 |  | NEW |  |  | 0 | AllplanAttributes - Ortscode_Geschoßbezeichnung: E00; Sicherheitsklasse: -
 | H2 Ebene 0 | WA-TP | 1105Wa 0000003100 | yes |  | m² | Zimmer- und Holzbauarbeiten | Wand | Außenwand 7-Schalig | WA-TP |  |  | 0 |  | NEW |  |  | 0 | AllplanAttributes - Ortscode_Geschoßbezeichnung: E00; Sicherheitsklasse: -
 | H2 Ebene 0 | WA-KL | 1105Wa 0000003096 | yes |  | m² | Zimmer- und Holzbauarbeiten | Wand | Außenwand 7-Schalig | WA-KL |  |  | 0 |  | NEW |  |  | 0 | AllplanAttributes - Ortscode_Geschoßbezeichnung: E00; Sicherheitsklasse: -
 | H2 Ebene 0 | WA-TL | 1105Wa 0000003092 | yes |  | m² | Zimmer- und Holzbauarbeiten | Wand | Außenwand 7-Schalig | WA-TL |  |  | 0 |  | NEW |  |  | 0 | AllplanAttributes - Ortscode_Geschoßbezeichnung: E00; Sicherheitsklasse: -
 | H2 Ebene 0 | WA-HS | 1105Wa 0000003088 | yes |  | m² | Zimmer- und Holzbauarbeiten | Wand | Außenwand 7-Schalig | WA-HS |  |  | 0 |  | NEW |  |  | 0 | AllplanAttributes - Ortscode_Geschoßbezeichnung: E00; Sicherheitsklasse: -
 | H2 Ebene 0 | WA-LB | 1105Wa 0000003126 | yes |  | m² | Trockenbauarbeiten | Wand | Außenwand 7-Schalig | WA-LB |  |  | 0 |  | NEW |  |  | 0 | AllplanAttributes - Ortscode_Geschoßbezeichnung: E00; ash_W_Trockenbau_Qualitäten: 6; Sicherheitsklasse: -
 | H2 Ebene 0 | WA-HD | 1105Wa 0000003124 | yes |  | m³ | Zimmer- und Holzbauarbeiten | Wand | Außenwand 7-Schalig | WA-HD |  |  | 0 |  | NEW |  |  | 0 | AllplanAttributes - Ortscode_Geschoßbezeichnung: E00; ash D_Detailverweis: DT B; ash D_Plannummer: D1851; Sicherheitsklasse: -
 | H2 Ebene 0 | WA-DL | 1105Wa 0000003122 | yes |  | m³ | Zimmer- und Holzbauarbeiten | Wand | Außenwand 7-Schalig | WA-DL |  |  | 0 |  | NEW |  |  | 0 | AllplanAttributes - Ortscode_Geschoßbezeichnung: E00; Sicherheitsklasse: -
 | H2 Ebene 0 | WA-TP | 1105Wa 0000003120 | yes |  | m² | Zimmer- und Holzbauarbeiten | Wand | Außenwand 7-Schalig | WA-TP |  |  | 0 |  | NEW |  |  | 0 | AllplanAttributes - Ortscode_Geschoßbezeichnung: E00; Sicherheitsklasse: -
 | H2 Ebene 0 | WA-KL | 1105Wa 0000003118 | yes |  | m² | Zimmer- und Holzbauarbeiten | Wand | Außenwand 7-Schalig | WA-KL |  |  | 0 |  | NEW |  |  | 0 | AllplanAttributes - Ortscode_Geschoßbezeichnung: E00; Sicherheitsklasse: -
 | H2 Ebene 0 | WA-TL | 1105Wa 0000003116 | yes |  | m² | Zimmer- und Holzbauarbeiten | Wand | Außenwand 7-Schalig | WA-TL |  |  | 0 |  | NEW |  |  | 0 | AllplanAttributes - Ortscode_Geschoßbezeichnung: E00; Sicherheitsklasse: -
 | H2 Ebene 0 | WA-HS | 1105Wa 0000003114 | yes |  | m² | Zimmer- und Holzbauarbeiten | Wand | Außenwand 7-Schalig | WA-HS |  |  | 0 |  | NEW |  |  | 0 | AllplanAttributes - Ortscode_Geschoßbezeichnung: E00; Sicherheitsklasse: -
 | H2 Ebene 0 | WA-LB | 1105Wa 0000002821 | yes |  | m² | Trockenbauarbeiten | Wand | Außenwand 7-Schalig | WA-LB |  |  | 0 |  | NEW |  |  | 0 | AllplanAttributes - Ortscode_Geschoßbezeichnung: E00; Sicherheitsklasse: -
 | H2 Ebene 0 | WA-HD | 1105Wa 0000002819 | yes |  | m³ | Zimmer- und Holzbauarbeiten | Wand | Außenwand 7-Schalig | WA-HD |  |  | 0 |  | NEW |  |  | 0 | AllplanAttributes - Ortscode_Geschoßbezeichnung: E00; ash D_Detailverweis: DT B; ash D_Plannummer: D1851; Sicherheitsklasse: -
 | H2 Ebene 0 | WA-DL | 1105Wa 0000002817 | yes |  | m³ | Zimmer- und Holzbauarbeiten | Wand | Außenwand 7-Schalig | WA-DL |  |  | 0 |  | NEW |  |  | 0 | AllplanAttributes - Ortscode_Geschoßbezeichnung: E00; Sicherheitsklasse: -
 | H2 Ebene 0 | WA-TP | 1105Wa 0000002815 | yes |  | m² | Zimmer- und Holzbauarbeiten | Wand | Außenwand 7-Schalig | WA-TP |  |  | 0 |  | NEW |  |  | 0 | AllplanAttributes - Ortscode_Geschoßbezeichnung: E00; Sicherheitsklasse: -
 | H2 Ebene 0 | WA-KL | 1105Wa 0000002813 | yes |  | m² | Zimmer- und Holzbauarbeiten | Wand | Außenwand 7-Schalig | WA-KL |  |  | 0 |  | NEW |  |  | 0 | AllplanAttributes - Ortscode_Geschoßbezeichnung: E00; Sicherheitsklasse: -
 | H2 Ebene 0 | WA-TL | 1105Wa 0000002811 | yes |  | m² | Zimmer- und Holzbauarbeiten | Wand | Außenwand 7-Schalig | WA-TL |  |  | 0 |  | NEW |  |  | 0 | AllplanAttributes - Ortscode_Geschoßbezeichnung: E00; Sicherheitsklasse: -
 | H2 Ebene 0 | WA-HS | 1105Wa 0000002809 | yes |  | m² | Zimmer- und Holzbauarbeiten | Wand | Außenwand 7-Schalig | WA-HS |  |  | 0 |  | NEW |  |  | 0 | AllplanAttributes - Ortscode_Geschoßbezeichnung: E00; Sicherheitsklasse: -
 | H2 Ebene 0 | WA-LB | 1105Wa 0000002807 | yes |  | m² | Trockenbauarbeiten | Wand | Außenwand 7-Schalig | WA-LB |  |  | 0 |  | NEW |  |  | 0 | AllplanAttributes - Ortscode_Geschoßbezeichnung: E00; Sicherheitsklasse: -
 | H2 Ebene 0 | WA-HD | 1105Wa 0000002803 | yes |  | m³ | Zimmer- und Holzbauarbeiten | Wand | Außenwand 7-Schalig | WA-HD |  |  | 0 |  | NEW |  |  | 0 | AllplanAttributes - Ortscode_Geschoßbezeichnung: E00; ash D_Detailverweis: DT B; ash D_Plannummer: D1851; Sicherheitsklasse: -
 | H2 Ebene 0 | WA-DL | 1105Wa 0000002799 | yes |  | m³ | Zimmer- und Holzbauarbeiten | Wand | Außenwand 7-Schalig | WA-DL |  |  | 0 |  | NEW |  |  | 0 | AllplanAttributes - Ortscode_Geschoßbezeichnung: E00; Sicherheitsklasse: -
 | H2 Ebene 0 | WA-TP | 1105Wa 0000002795 | yes |  | m² | Zimmer- und Holzbauarbeiten | Wand | Außenwand 7-Schalig | WA-TP |  |  | 0 |  | NEW |  |  | 0 | AllplanAttributes - Ortscode_Geschoßbezeichnung: E00; Sicherheitsklasse: -
 | H2 Ebene 0 | WA-KL | 1105Wa 0000002791 | yes |  | m² | Zimmer- und Holzbauarbeiten | Wand | Außenwand 7-Schalig | WA-KL |  |  | 0 |  | NEW |  |  | 0 | AllplanAttributes - Ortscode_Geschoßbezeichnung: E00; Sicherheitsklasse: -
 | H2 Ebene 0 | WA-TL | 1105Wa 0000002787 | yes |  | m² | Zimmer- und Holzbauarbeiten | Wand | Außenwand 7-Schalig | WA-TL |  |  | 0 |  | NEW |  |  | 0 | AllplanAttributes - Ortscode_Geschoßbezeichnung: E00; Sicherheitsklasse: -
 | H2 Ebene 0 | WA-HS | 1105Wa 0000002783 | yes |  | m² | Zimmer- und Holzbauarbeiten | Wand | Außenwand 7-Schalig | WA-HS |  |  | 0 |  | NEW |  |  | 0 | AllplanAttributes - Ortscode_Geschoßbezeichnung: E00; Sicherheitsklasse: -
 | H2 Ebene 0 | WA-LB | 1105Wa 0000002572 | yes |  | m² | Trockenbauarbeiten | Wand | Außenwand 7-Schalig | WA-LB |  |  | 0 |  | NEW |  |  | 0 | AllplanAttributes - Ortscode_Geschoßbezeichnung: E00; Sicherheitsklasse: -
 | H2 Ebene 0 | WA-HD | 1105Wa 0000002576 | yes |  | m³ | Zimmer- und Holzbauarbeiten | Wand | Außenwand 7-Schalig | WA-HD |  |  | 0 |  | NEW |  |  | 0 | AllplanAttributes - Ortscode_Geschoßbezeichnung: E00; ash D_Detailverweis: DT C; ash D_Plannummer: D1851; Sicherheitsklasse: -
 | H2 Ebene 0 | WA-DL | 1105Wa 0000002580 | yes |  | m³ | Zimmer- und Holzbauarbeiten | Wand | Außenwand 7-Schalig | WA-DL |  |  | 0 |  | NEW |  |  | 0 | AllplanAttributes - Ortscode_Geschoßbezeichnung: E00; Sicherheitsklasse: -
 | H2 Ebene 0 | WA-TP | 1105Wa 0000002584 | yes |  | m² | Zimmer- und Holzbauarbeiten | Wand | Außenwand 7-Schalig | WA-TP |  |  | 0 |  | NEW |  |  | 0 | AllplanAttributes - Ortscode_Geschoßbezeichnung: E00; Sicherheitsklasse: -
 | H2 Ebene 0 | WA-KL | 1105Wa 0000002588 | yes |  | m² | Zimmer- und Holzbauarbeiten | Wand | Außenwand 7-Schalig | WA-KL |  |  | 0 |  | NEW |  |  | 0 | AllplanAttributes - Ortscode_Geschoßbezeichnung: E00; Sicherheitsklasse: -
 | H2 Ebene 0 | WA-TL | 1105Wa 0000002592 | yes |  | m² | Zimmer- und Holzbauarbeiten | Wand | Außenwand 7-Schalig | WA-TL |  |  | 0 |  | NEW |  |  | 0 | AllplanAttributes - Ortscode_Geschoßbezeichnung: E00; Sicherheitsklasse: -
 | H2 Ebene 0 | WA-HS | 1105Wa 0000002596 | yes |  | m² | Zimmer- und Holzbauarbeiten | Wand | Außenwand 7-Schalig | WA-HS |  |  | 0 |  | NEW |  |  | 0 | AllplanAttributes - Ortscode_Geschoßbezeichnung: E00; Sicherheitsklasse: -
 | H2 Ebene 0 | WA-LB | 1105Wa 0000002556 | yes |  | m² | Trockenbauarbeiten | Wand | Außenwand 7-Schalig | WA-LB |  |  | 0 |  | NEW |  |  | 0 | AllplanAttributes - Ortscode_Geschoßbezeichnung: E00; Sicherheitsklasse: -
 | H2 Ebene 0 | WA-HD | 1105Wa 0000002554 | yes |  | m³ | Zimmer- und Holzbauarbeiten | Wand | Außenwand 7-Schalig | WA-HD |  |  | 0 |  | NEW |  |  | 0 | AllplanAttributes - Ortscode_Geschoßbezeichnung: E00; ash D_Detailverweis: DT C / D; ash D_Plannummer: D1851; Sicherheitsklasse: -
 | H2 Ebene 0 | WA-DL | 1105Wa 0000002552 | yes |  | m³ | Zimmer- und Holzbauarbeiten | Wand | Außenwand 7-Schalig | WA-DL |  |  | 0 |  | NEW |  |  | 0 | AllplanAttributes - Ortscode_Geschoßbezeichnung: E00; Sicherheitsklasse: -
 | H2 Ebene 0 | WA-TP | 1105Wa 0000002550 | yes |  | m² | Zimmer- und Holzbauarbeiten | Wand | Außenwand 7-Schalig | WA-TP |  |  | 0 |  | NEW |  |  | 0 | AllplanAttributes - Ortscode_Geschoßbezeichnung: E00; Sicherheitsklasse: -
 | H2 Ebene 0 | WA-KL | 1105Wa 0000002548 | yes |  | m² | Zimmer- und Holzbauarbeiten | Wand | Außenwand 7-Schalig | WA-KL |  |  | 0 |  | NEW |  |  | 0 | AllplanAttributes - Ortscode_Geschoßbezeichnung: E00; Sicherheitsklasse: -
 | H2 Ebene 0 | WA-TL | 1105Wa 0000002546 | yes |  | m² | Zimmer- und Holzbauarbeiten | Wand | Außenwand 7-Schalig | WA-TL |  |  | 0 |  | NEW |  |  | 0 | AllplanAttributes - Ortscode_Geschoßbezeichnung: E00; Sicherheitsklasse: -
 | H2 Ebene 0 | WA-HS | 1105Wa 0000002544 | yes |  | m² | Zimmer- und Holzbauarbeiten | Wand | Außenwand 7-Schalig | WA-HS |  |  | 0 |  | NEW |  |  | 0 | AllplanAttributes - Ortscode_Geschoßbezeichnung: E00; Sicherheitsklasse: -
 | H2 Ebene 0 | WA-LB | 1105Wa 0000034413 | yes |  | m² | Trockenbauarbeiten | Wand | Außenwand 7-Schalig | WA-LB |  |  | 0 |  | NEW |  |  | 0 | AllplanAttributes - Ortscode_Geschoßbezeichnung: E00; Sicherheitsklasse: -
 | H2 Ebene 0 | WA-HD | 1105Wa 0000034414 | yes |  | m³ | Zimmer- und Holzbauarbeiten | Wand | Außenwand 7-Schalig | WA-HD |  |  | 0 |  | NEW |  |  | 0 | AllplanAttributes - Ortscode_Geschoßbezeichnung: E00; ash D_Detailverweis: DT D; ash D_Plannummer: D1851; Sicherheitsklasse: -
 | H2 Ebene 0 | WA-DL | 1105Wa 0000034415 | yes |  | m³ | Zimmer- und Holzbauarbeiten | Wand | Außenwand 7-Schalig | WA-DL |  |  | 0 |  | NEW |  |  | 0 | AllplanAttributes - Ortscode_Geschoßbezeichnung: E00; Sicherheitsklasse: -
 | H2 Ebene 0 | WA-TP | 1105Wa 0000034416 | yes |  | m² | Zimmer- und Holzbauarbeiten | Wand | Außenwand 7-Schalig | WA-TP |  |  | 0 |  | NEW |  |  | 0 | AllplanAttributes - Ortscode_Geschoßbezeichnung: E00; Sicherheitsklasse: -
 | H2 Ebene 0 | WA-KL | 1105Wa 0000034417 | yes |  | m² | Zimmer- und Holzbauarbeiten | Wand | Außenwand 7-Schalig | WA-KL |  |  | 0 |  | NEW |  |  | 0 | AllplanAttributes - Ortscode_Geschoßbezeichnung: E00; Sicherheitsklasse: -
 | H2 Ebene 0 | WA-TL | 1105Wa 0000034418 | yes |  | m² | Zimmer- und Holzbauarbeiten | Wand | Außenwand 7-Schalig | WA-TL |  |  | 0 |  | NEW |  |  | 0 | AllplanAttributes - Ortscode_Geschoßbezeichnung: E00; Sicherheitsklasse: -
 | H2 Ebene 0 | WA-HS | 1105Wa 0000034419 | yes |  | m² | Zimmer- und Holzbauarbeiten | Wand | Außenwand 7-Schalig | WA-HS |  |  | 0 |  | NEW |  |  | 0 | AllplanAttributes - Ortscode_Geschoßbezeichnung: E00; Sicherheitsklasse: -
 | H2 Ebene 0 | WA-LB | 1105Wa 0000001277 | yes |  | m² | Trockenbauarbeiten | Wand | Außenwand 7-Schalig | WA-LB |  |  | 0 |  |  |  |  | 0 | AllplanAttributes - Ortscode_Geschoßbezeichnung: E00; Sicherheitsklasse: -
 | H2 Ebene 0 | WA-HD | 1105Wa 0000001301 | yes |  | m³ | Zimmer- und Holzbauarbeiten | Wand | Außenwand 7-Schalig | WA-HD |  |  | 0 |  |  |  |  | 0 | AllplanAttributes - Ortscode_Geschoßbezeichnung: E00; ash D_Detailverweis: DT C / D; ash D_Plannummer: D1851; Sicherheitsklasse: -
 | H2 Ebene 0 | WA-DL | 1105Wa 0000001303 | yes |  | m³ | Zimmer- und Holzbauarbeiten | Wand | Außenwand 7-Schalig | WA-DL |  |  | 0 |  |  |  |  | 0 | AllplanAttributes - Ortscode_Geschoßbezeichnung: E00; Sicherheitsklasse: -
 | H2 Ebene 0 | WA-TP | 1105Wa 0000001305 | yes |  | m² | Zimmer- und Holzbauarbeiten | Wand | Außenwand 7-Schalig | WA-TP |  |  | 0 |  |  |  |  | 0 | AllplanAttributes - Ortscode_Geschoßbezeichnung: E00; Sicherheitsklasse: -
 | H2 Ebene 0 | WA-KL | 1105Wa 0000001307 | yes |  | m² | Zimmer- und Holzbauarbeiten | Wand | Außenwand 7-Schalig | WA-KL |  |  | 0 |  |  |  |  | 0 | AllplanAttributes - Ortscode_Geschoßbezeichnung: E00; Sicherheitsklasse: -
 | H2 Ebene 0 | WA-TL | 1105Wa 0000001309 | yes |  | m² | Zimmer- und Holzbauarbeiten | Wand | Außenwand 7-Schalig | WA-TL |  |  | 0 |  |  |  |  | 0 | AllplanAttributes - Ortscode_Geschoßbezeichnung: E00; Sicherheitsklasse: -
 | H2 Ebene 0 | WA-HS | 1105Wa 0000001311 | yes |  | m² | Zimmer- und Holzbauarbeiten | Wand | Außenwand 7-Schalig | WA-HS |  |  | 0 |  |  |  |  | 0 | AllplanAttributes - Ortscode_Geschoßbezeichnung: E00; Sicherheitsklasse: -
 | H2 Ebene 0 | WA-LB | 1105Wa 0811567043 | yes |  | m² | Trockenbauarbeiten | Wand | Außenwand 7-Schalig | WA-LB |  |  | 0 |  | NEW |  |  | 0 | AllplanAttributes - Ortscode_Geschoßbezeichnung: E00; Sicherheitsklasse: -
 | H2 Ebene 0 | WA-HD | 1105Wa 0811567042 | yes |  | m³ | Zimmer- und Holzbauarbeiten | Wand | Außenwand 7-Schalig | WA-HD |  |  | 0 |  | NEW |  |  | 0 | AllplanAttributes - Ortscode_Geschoßbezeichnung: E00; ash D_Detailverweis: DT A; ash D_Plannummer: D1850; Sicherheitsklasse: -
 | H2 Ebene 0 | WA-DL | 1105Wa 0811567041 | yes |  | m³ | Zimmer- und Holzbauarbeiten | Wand | Außenwand 7-Schalig | WA-DL |  |  | 0 |  | NEW |  |  | 0 | AllplanAttributes - Ortscode_Geschoßbezeichnung: E00; Sicherheitsklasse: -
 | H2 Ebene 0 | WA-TP | 1105Wa 0811567040 | yes |  | m² | Zimmer- und Holzbauarbeiten | Wand | Außenwand 7-Schalig | WA-TP |  |  | 0 |  | NEW |  |  | 0 | AllplanAttributes - Ortscode_Geschoßbezeichnung: E00; Sicherheitsklasse: -
 | H2 Ebene 0 | WA-KL | 1105Wa 0811567039 | yes |  | m² | Zimmer- und Holzbauarbeiten | Wand | Außenwand 7-Schalig | WA-KL |  |  | 0 |  | NEW |  |  | 0 | AllplanAttributes - Ortscode_Geschoßbezeichnung: E00; Sicherheitsklasse: -
 | H2 Ebene 0 | WA-TL | 1105Wa 0811567038 | yes |  | m² | Zimmer- und Holzbauarbeiten | Wand | Außenwand 7-Schalig | WA-TL |  |  | 0 |  | NEW |  |  | 0 | AllplanAttributes - Ortscode_Geschoßbezeichnung: E00; Sicherheitsklasse: -
 | H2 Ebene 0 | WA-HS | 1105Wa 0811567037 | yes |  | m² | Zimmer- und Holzbauarbeiten | Wand | Außenwand 7-Schalig | WA-HS |  |  | 0 |  | NEW |  |  | 0 | AllplanAttributes - Ortscode_Geschoßbezeichnung: E00; Sicherheitsklasse: -
 | H2 Ebene 0 | WA-LB | 1105Wa 0811567313 | yes |  | m² | Trockenbauarbeiten | Wand | Außenwand 7-Schalig | WA-LB |  |  | 0 |  | NEW |  |  | 0 | AllplanAttributes - Ortscode_Geschoßbezeichnung: E00; Sicherheitsklasse: -
 | H2 Ebene 0 | WA-HD | 1105Wa 0811567314 | yes |  | m³ | Zimmer- und Holzbauarbeiten | Wand | Außenwand 7-Schalig | WA-HD |  |  | 0 |  | NEW |  |  | 0 | AllplanAttributes - Ortscode_Geschoßbezeichnung: E00; ash D_Detailverweis: DT D; ash D_Plannummer: D1851; Sicherheitsklasse: -
 | H2 Ebene 0 | WA-DL | 1105Wa 0811567315 | yes |  | m³ | Zimmer- und Holzbauarbeiten | Wand | Außenwand 7-Schalig | WA-DL |  |  | 0 |  | NEW |  |  | 0 | AllplanAttributes - Ortscode_Geschoßbezeichnung: E00; Sicherheitsklasse: -
 | H2 Ebene 0 | WA-TP | 1105Wa 0811567316 | yes |  | m² | Zimmer- und Holzbauarbeiten | Wand | Außenwand 7-Schalig | WA-TP |  |  | 0 |  | NEW |  |  | 0 | AllplanAttributes - Ortscode_Geschoßbezeichnung: E00; Sicherheitsklasse: -
 | H2 Ebene 0 | WA-KL | 1105Wa 0811567317 | yes |  | m² | Zimmer- und Holzbauarbeiten | Wand | Außenwand 7-Schalig | WA-KL |  |  | 0 |  | NEW |  |  | 0 | AllplanAttributes - Ortscode_Geschoßbezeichnung: E00; Sicherheitsklasse: -
 | H2 Ebene 0 | WA-TL | 1105Wa 0811567318 | yes |  | m² | Zimmer- und Holzbauarbeiten | Wand | Außenwand 7-Schalig | WA-TL |  |  | 0 |  | NEW |  |  | 0 | AllplanAttributes - Ortscode_Geschoßbezeichnung: E00; Sicherheitsklasse: -
 | H2 Ebene 0 | WA-HS | 1105Wa 0811567319 | yes |  | m² | Zimmer- und Holzbauarbeiten | Wand | Außenwand 7-Schalig | WA-HS |  |  | 0 |  | NEW |  |  | 0 | AllplanAttributes - Ortscode_Geschoßbezeichnung: E00; Sicherheitsklasse: -
 | H2 Ebene 0 | WA-LB | 1105Wa 0000002019 | yes |  | m² | Trockenbauarbeiten | Wand | Außenwand 7-Schalig | WA-LB |  |  | 0 |  | NEW |  |  | 0 | AllplanAttributes - Ortscode_Geschoßbezeichnung: E00; Sicherheitsklasse: -
 | H2 Ebene 0 | WA-HD | 1105Wa 0000002017 | yes |  | m³ | Zimmer- und Holzbauarbeiten | Wand | Außenwand 7-Schalig | WA-HD |  |  | 0 |  | NEW |  |  | 0 | AllplanAttributes - Ortscode_Geschoßbezeichnung: E00; ash D_Detailverweis: DT C / D; ash D_Plannummer: D1851; Sicherheitsklasse: -
 | H2 Ebene 0 | WA-DL | 1105Wa 0000002015 | yes |  | m³ | Zimmer- und Holzbauarbeiten | Wand | Außenwand 7-Schalig | WA-DL |  |  | 0 |  | NEW |  |  | 0 | AllplanAttributes - Ortscode_Geschoßbezeichnung: E00; Sicherheitsklasse: -
 | H2 Ebene 0 | WA-TP | 1105Wa 0000002013 | yes |  | m² | Zimmer- und Holzbauarbeiten | Wand | Außenwand 7-Schalig | WA-TP |  |  | 0 |  | NEW |  |  | 0 | AllplanAttributes - Ortscode_Geschoßbezeichnung: E00; Sicherheitsklasse: -
 | H2 Ebene 0 | WA-KL | 1105Wa 0000002011 | yes |  | m² | Zimmer- und Holzbauarbeiten | Wand | Außenwand 7-Schalig | WA-KL |  |  | 0 |  | NEW |  |  | 0 | AllplanAttributes - Ortscode_Geschoßbezeichnung: E00; Sicherheitsklasse: -
 | H2 Ebene 0 | WA-TL | 1105Wa 0000002009 | yes |  | m² | Zimmer- und Holzbauarbeiten | Wand | Außenwand 7-Schalig | WA-TL |  |  | 0 |  | NEW |  |  | 0 | AllplanAttributes - Ortscode_Geschoßbezeichnung: E00; Sicherheitsklasse: -
 | H2 Ebene 0 | WA-HS | 1105Wa 0000002007 | yes |  | m² | Zimmer- und Holzbauarbeiten | Wand | Außenwand 7-Schalig | WA-HS |  |  | 0 |  | NEW |  |  | 0 | AllplanAttributes - Ortscode_Geschoßbezeichnung: E00; Sicherheitsklasse: -
 | H2 Ebene 0 | WA-LB | 1105Wa 0000002063 | yes |  | m² | Trockenbauarbeiten | Wand | Außenwand 7-Schalig | WA-LB |  |  | 0 |  | NEW |  |  | 0 | AllplanAttributes - Ortscode_Geschoßbezeichnung: E00; Sicherheitsklasse: -
 | H2 Ebene 0 | WA-HD | 1105Wa 0000002059 | yes |  | m³ | Zimmer- und Holzbauarbeiten | Wand | Außenwand 7-Schalig | WA-HD |  |  | 0 |  | NEW |  |  | 0 | AllplanAttributes - Ortscode_Geschoßbezeichnung: E00; ash D_Detailverweis: DT C; ash D_Plannummer: D1851; Sicherheitsklasse: -
 | H2 Ebene 0 | WA-DL | 1105Wa 0000002055 | yes |  | m³ | Zimmer- und Holzbauarbeiten | Wand | Außenwand 7-Schalig | WA-DL |  |  | 0 |  | NEW |  |  | 0 | AllplanAttributes - Ortscode_Geschoßbezeichnung: E00; Sicherheitsklasse: -
 | H2 Ebene 0 | WA-TP | 1105Wa 0000002051 | yes |  | m² | Zimmer- und Holzbauarbeiten | Wand | Außenwand 7-Schalig | WA-TP |  |  | 0 |  | NEW |  |  | 0 | AllplanAttributes - Ortscode_Geschoßbezeichnung: E00; Sicherheitsklasse: -
 | H2 Ebene 0 | WA-KL | 1105Wa 0000002047 | yes |  | m² | Zimmer- und Holzbauarbeiten | Wand | Außenwand 7-Schalig | WA-KL |  |  | 0 |  | NEW |  |  | 0 | AllplanAttributes - Ortscode_Geschoßbezeichnung: E00; Sicherheitsklasse: -
 | H2 Ebene 0 | WA-TL | 1105Wa 0000002043 | yes |  | m² | Zimmer- und Holzbauarbeiten | Wand | Außenwand 7-Schalig | WA-TL |  |  | 0 |  | NEW |  |  | 0 | AllplanAttributes - Ortscode_Geschoßbezeichnung: E00; Sicherheitsklasse: -
 | H2 Ebene 0 | WA-HS | 1105Wa 0000002039 | yes |  | m² | Zimmer- und Holzbauarbeiten | Wand | Außenwand 7-Schalig | WA-HS |  |  | 0 |  | NEW |  |  | 0 | AllplanAttributes - Ortscode_Geschoßbezeichnung: E00; Sicherheitsklasse: -
 | H2 Ebene 0 | WI-HW 60 | 1105Wa 0000020351 | yes |  | m³ | Zimmer- und Holzbauarbeiten | Wand | Außenwand 7-Schalig | WI-HW 60 |  |  | 0 |  |  |  |  | 0 | AllplanAttributes - Ortscode_Geschoßbezeichnung: E00; ash D_Detailverweis: X8; ash D_Plannummer: D1861; Sicherheitsklasse: -
 | H2 Ebene 0 | WA-LB | 1105Wa 0000003947 | yes |  | m² | Trockenbauarbeiten | Wand | Außenwand 7-Schalig | WA-LB |  |  | 0 |  |  |  |  | 0 | AllplanAttributes - Ortscode_Geschoßbezeichnung: E00; Sicherheitsklasse: -
 | H2 Ebene 0 | WA-HD | 1105Wa 0000003957 | yes |  | m³ | Zimmer- und Holzbauarbeiten | Wand | Außenwand 7-Schalig | WA-HD |  |  | 0 |  |  |  |  | 0 | AllplanAttributes - Ortscode_Geschoßbezeichnung: E00; ash D_Detailverweis: DT D; ash D_Plannummer: D1851; Sicherheitsklasse: -
 | H2 Ebene 0 | WA-DL | 1105Wa 0000003966 | yes |  | m³ | Zimmer- und Holzbauarbeiten | Wand | Außenwand 7-Schalig | WA-DL |  |  | 0 |  |  |  |  | 0 | AllplanAttributes - Ortscode_Geschoßbezeichnung: E00; Sicherheitsklasse: -
 | H2 Ebene 0 | WA-LB | 1105Wa 0000003976 | yes |  | m² | Trockenbauarbeiten | Wand | Außenwand 7-Schalig | WA-LB |  |  | 0 |  |  |  |  | 0 | AllplanAttributes - Ortscode_Geschoßbezeichnung: E00; Sicherheitsklasse: -
 | H2 Ebene 0 | WA-KL | 1105Wa 0000003986 | yes |  | m² | Zimmer- und Holzbauarbeiten | Wand | Außenwand 7-Schalig | WA-KL |  |  | 0 |  |  |  |  | 0 | AllplanAttributes - Ortscode_Geschoßbezeichnung: E00; Sicherheitsklasse: -
 | H2 Ebene 0 | WA-TL | 1105Wa 0000003996 | yes |  | m² | Zimmer- und Holzbauarbeiten | Wand | Außenwand 7-Schalig | WA-TL |  |  | 0 |  |  |  |  | 0 | AllplanAttributes - Ortscode_Geschoßbezeichnung: E00; Sicherheitsklasse: -
 | H2 Ebene 0 | WA-HS | 1105Wa 0000004006 | yes |  | m² | Zimmer- und Holzbauarbeiten | Wand | Außenwand 7-Schalig | WA-HS |  |  | 0 |  |  |  |  | 0 | AllplanAttributes - Ortscode_Geschoßbezeichnung: E00; Sicherheitsklasse: -
 | H2 Ebene 0 | WA-LB | 1105Wa 0000061940 | yes |  | m² | Trockenbauarbeiten | Wand | Außenwand 7-Schalig | WA-LB |  |  | 0 |  |  |  |  | 0 | AllplanAttributes - Ortscode_Geschoßbezeichnung: E00; Sicherheitsklasse: -
 | H2 Ebene 0 | WA-HD | 1105Wa 0000061944 | yes |  | m³ | Zimmer- und Holzbauarbeiten | Wand | Außenwand 7-Schalig | WA-HD |  |  | 0 |  |  |  |  | 0 | AllplanAttributes - Ortscode_Geschoßbezeichnung: E00; ash D_Detailverweis: DT C / D; ash D_Plannummer: D1851; Sicherheitsklasse: -
 | H2 Ebene 0 | WA-DL | 1105Wa 0000061974 | yes |  | m³ | Zimmer- und Holzbauarbeiten | Wand | Außenwand 7-Schalig | WA-DL |  |  | 0 |  |  |  |  | 0 | AllplanAttributes - Ortscode_Geschoßbezeichnung: E00; Sicherheitsklasse: -
 | H2 Ebene 0 | WA-TP | 1105Wa 0000061979 | yes |  | m² | Zimmer- und Holzbauarbeiten | Wand | Außenwand 7-Schalig | WA-TP |  |  | 0 |  |  |  |  | 0 | AllplanAttributes - Ortscode_Geschoßbezeichnung: E00; Sicherheitsklasse: -
 | H2 Ebene 0 | WA-KL | 1105Wa 0000061963 | yes |  | m² | Zimmer- und Holzbauarbeiten | Wand | Außenwand 7-Schalig | WA-KL |  |  | 0 |  |  |  |  | 0 | AllplanAttributes - Ortscode_Geschoßbezeichnung: E00; Sicherheitsklasse: -
 | H2 Ebene 0 | WA-TL | 1105Wa 0000061959 | yes |  | m² | Zimmer- und Holzbauarbeiten | Wand | Außenwand 7-Schalig | WA-TL |  |  | 0 |  |  |  |  | 0 | AllplanAttributes - Ortscode_Geschoßbezeichnung: E00; Sicherheitsklasse: -
 | H2 Ebene 0 | WA-HS | 1105Wa 0000061967 | yes |  | m² | Zimmer- und Holzbauarbeiten | Wand | Außenwand 7-Schalig | WA-HS |  |  | 0 |  |  |  |  | 0 | AllplanAttributes - Ortscode_Geschoßbezeichnung: E00; Sicherheitsklasse: -
 | H2 Ebene 0 | WA-LB | 1105Wa 0000002699 | yes |  | m² | Trockenbauarbeiten | Wand | Außenwand 7-Schalig | WA-LB |  |  | 0 |  | NEW |  |  | 0 | AllplanAttributes - Ortscode_Geschoßbezeichnung: E00; Sicherheitsklasse: -
 | H2 Ebene 0 | WA-HD | 1105Wa 0000002706 | yes |  | m³ | Zimmer- und Holzbauarbeiten | Wand | Außenwand 7-Schalig | WA-HD |  |  | 0 |  | NEW |  |  | 0 | AllplanAttributes - Ortscode_Geschoßbezeichnung: E00; ash D_Detailverweis: DT C; ash D_Plannummer: D1851; Sicherheitsklasse: -
 | H2 Ebene 0 | WA-DL | 1105Wa 0000002713 | yes |  | m³ | Zimmer- und Holzbauarbeiten | Wand | Außenwand 7-Schalig | WA-DL |  |  | 0 |  | NEW |  |  | 0 | AllplanAttributes - Ortscode_Geschoßbezeichnung: E00; Sicherheitsklasse: -
 | H2 Ebene 0 | WA-TP | 1105Wa 0000002720 | yes |  | m² | Zimmer- und Holzbauarbeiten | Wand | Außenwand 7-Schalig | WA-TP |  |  | 0 |  | NEW |  |  | 0 | AllplanAttributes - Ortscode_Geschoßbezeichnung: E00; Sicherheitsklasse: -
 | H2 Ebene 0 | WA-KL | 1105Wa 0000002727 | yes |  | m² | Zimmer- und Holzbauarbeiten | Wand | Außenwand 7-Schalig | WA-KL |  |  | 0 |  | NEW |  |  | 0 | AllplanAttributes - Ortscode_Geschoßbezeichnung: E00; Sicherheitsklasse: -
 | H2 Ebene 0 | WA-TL | 1105Wa 0000002734 | yes |  | m² | Zimmer- und Holzbauarbeiten | Wand | Außenwand 7-Schalig | WA-TL |  |  | 0 |  | NEW |  |  | 0 | AllplanAttributes - Ortscode_Geschoßbezeichnung: E00; Sicherheitsklasse: -
 | H2 Ebene 0 | WA-HS | 1105Wa 0000002741 | yes |  | m² | Zimmer- und Holzbauarbeiten | Wand | Außenwand 7-Schalig | WA-HS |  |  | 0 |  | NEW |  |  | 0 | AllplanAttributes - Ortscode_Geschoßbezeichnung: E00; Sicherheitsklasse: -
 | H2 Ebene 0 | WA-FAS | 1105Wa 0811686006 | yes | Codetext | m² | Vorgehängte Fassaden | Wand | Außenwand mehrschalig | WA-FAS | 0 | A |  | 1106HWa0000000475 | NEW | no | yes | 0 | 0 | no | 0 | no | Codetext
 | H2 Ebene 0 | WA-FAS | 1105Wa 0811686039 | yes | Codetext | m² | Vorgehängte Fassaden | Wand | Außenwand mehrschalig | WA-FAS | 0 | A |  | 1106HWa0000000475 | NEW | no | yes | 0 | 0 | no | 0 | no | Codetext
 | H2 Ebene 0 | WI-SYS | 1105Wa 0811686040 | yes | Codetext | m² | Trockenbauarbeiten | Wand | Außenwand mehrschalig | WI-SYS | 0 | A |  |  | NEW | no | yes | 0 | 0 | no | 0 | no | Codetext
 | H2 Ebene 0 | WA-FAS | 1105Wa 0811686239 | yes | Codetext | m² | Vorgehängte Fassaden | Wand | Außenwand mehrschalig | WA-FAS | 0 | A |  | 1106HWa0000000475 | NEW | no | yes | 0 | 0 | no | 0 | no | Codetext
 | H2 Ebene 0 | WA-FAS | 1105Wa 0811686240 | yes | Codetext | m² | Vorgehängte Fassaden | Wand | Außenwand mehrschalig | WA-FAS | 0 | A |  | 1106HWa0000000475 | NEW | no | yes | 0 | 0 | no | 0 | no | Codetext
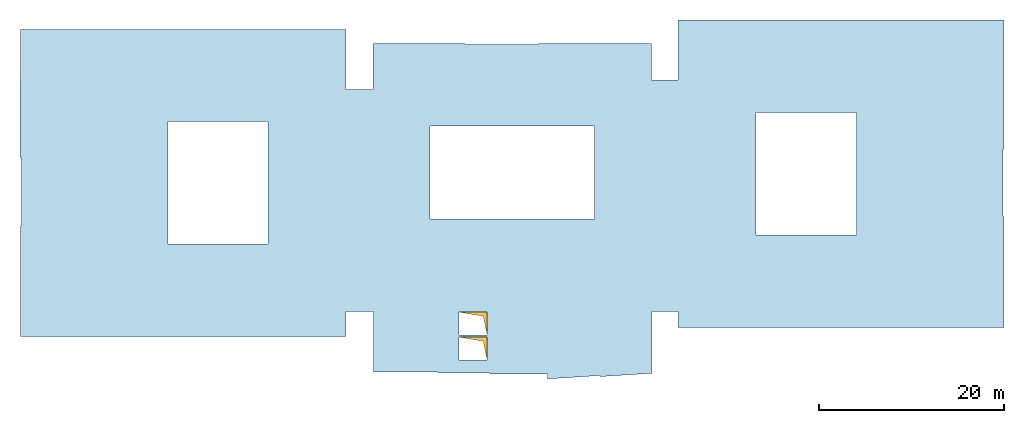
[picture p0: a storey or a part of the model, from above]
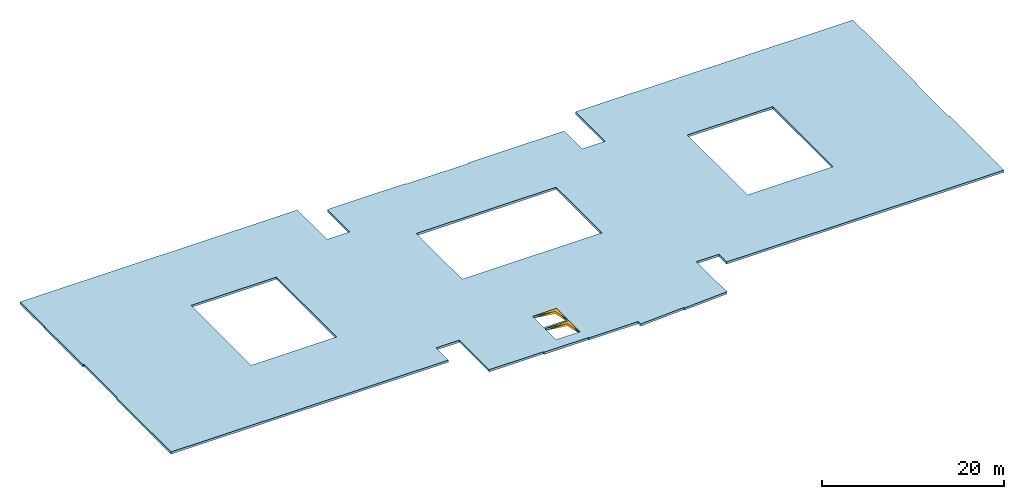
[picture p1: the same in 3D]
Properties of the parts of a building model (IFC4), part 71 of 80

# IfcWall (6826)
Name | In | Material | Allright_Bauteil_ID | 2D Interaktion | Codetext | Abrechnungsart | Gewerk | Objektname | Bezeichnung | AllplanAttributes, Material | Typ = SurfaceSpreadOfFlame | Brandschutzklasse | OKFF | P_ID | Status | LoadBearing | IsExternal | FireRating | ThermalTransmittance (W/K/m2) | Combustible | AcousticRating | Compartmentation | Reference
 | H2 Ebene 0 | WA-FAS | 1105Wa 2005674042 | yes | Codetext | m² | Vorgehängte Fassaden | Wand | Außenwand mehrschalig | WA-FAS | 0 | A |  | 1106HWa0000000475 | NEW | no | yes | 0 | 0 | no | 0 | no | Codetext
 | H2 Ebene 0 | WA-FAS | 1105Wa 2005674041 | yes | Codetext | m² | Vorgehängte Fassaden | Wand | Außenwand mehrschalig | WA-FAS | 0 | A |  | 1106HWa0000000475 | NEW | no | yes | 0 | 0 | no | 0 | no | Codetext
 | H2 Ebene 0 | WI-SYS | 1105Wa 2005674040 | yes | Codetext | m² | Trockenbauarbeiten | Wand | Außenwand mehrschalig | WI-SYS | 0 | A |  |  | NEW | no | yes | 0 | 0 | no | 0 | no | Codetext
 | H2 Ebene 0 | WA-FAS | 1105Wa 2005674039 | yes | Codetext | m² | Vorgehängte Fassaden | Wand | Außenwand mehrschalig | WA-FAS | 0 | A |  | 1106HWa0000000475 | NEW | no | yes | 0 | 0 | no | 0 | no | Codetext
 | H2 Ebene 0 | WA-FAS | 1105Wa 2005674038 | yes | Codetext | m² | Vorgehängte Fassaden | Wand | Außenwand mehrschalig | WA-FAS | 0 | A |  | 1106HWa0000000475 | NEW | no | yes | 0 | 0 | no | 0 | no | Codetext
 | H2 Ebene 0 | WA-LB | 1105Wa 0000001846 | yes |  | m² | Trockenbauarbeiten | Wand | Außenwand 7-Schalig | WA-LB |  |  | 0 |  |  |  |  | 0 | AllplanAttributes - Ortscode_Geschoßbezeichnung: E00; Sicherheitsklasse: -
 | H2 Ebene 0 | WA-HD | 1105Wa 0000001844 | yes |  | m³ | Zimmer- und Holzbauarbeiten | Wand | Außenwand 7-Schalig | WA-HD |  |  | 0 |  |  |  |  | 0 | AllplanAttributes - Ortscode_Geschoßbezeichnung: E00; ash D_Detailverweis: DT C / D; ash D_Plannummer: D1851; Sicherheitsklasse: -
 | H2 Ebene 0 | WA-DL | 1105Wa 0000001842 | yes |  | m³ | Zimmer- und Holzbauarbeiten | Wand | Außenwand 7-Schalig | WA-DL |  |  | 0 |  |  |  |  | 0 | AllplanAttributes - Ortscode_Geschoßbezeichnung: E00; Sicherheitsklasse: -
 | H2 Ebene 0 | WA-TP | 1105Wa 0000001840 | yes |  | m² | Zimmer- und Holzbauarbeiten | Wand | Außenwand 7-Schalig | WA-TP |  |  | 0 |  |  |  |  | 0 | AllplanAttributes - Ortscode_Geschoßbezeichnung: E00; Sicherheitsklasse: -
 | H2 Ebene 0 | WA-KL | 1105Wa 0000001838 | yes |  | m² | Zimmer- und Holzbauarbeiten | Wand | Außenwand 7-Schalig | WA-KL |  |  | 0 |  |  |  |  | 0 | AllplanAttributes - Ortscode_Geschoßbezeichnung: E00; Sicherheitsklasse: -
 | H2 Ebene 0 | WA-TL | 1105Wa 0000001836 | yes |  | m² | Zimmer- und Holzbauarbeiten | Wand | Außenwand 7-Schalig | WA-TL |  |  | 0 |  |  |  |  | 0 | AllplanAttributes - Ortscode_Geschoßbezeichnung: E00; Sicherheitsklasse: -
 | H2 Ebene 0 | WA-HS | 1105Wa 0000001834 | yes |  | m² | Zimmer- und Holzbauarbeiten | Wand | Außenwand 7-Schalig | WA-HS |  |  | 0 |  |  |  |  | 0 | AllplanAttributes - Ortscode_Geschoßbezeichnung: E00; Sicherheitsklasse: -
 | H2 Ebene 0 | WA-LB | 1105Wa 2005677951 | yes |  | m² | Trockenbauarbeiten | Wand | Außenwand 7-Schalig | WA-LB |  |  | 0 |  | NEW |  |  | 0 | AllplanAttributes - Ortscode_Geschoßbezeichnung: E00; Sicherheitsklasse: -
 | H2 Ebene 0 | WA-LB | 1105Wa 2005677956 | yes |  | m² | Trockenbauarbeiten | Wand | Außenwand 7-Schalig | WA-LB |  |  | 0 |  | NEW |  |  | 0 | AllplanAttributes - Ortscode_Geschoßbezeichnung: E00; Sicherheitsklasse: -
 | H2 Ebene 0 | WA-HD | 1105Wa 2005677954 | yes |  | m³ | Zimmer- und Holzbauarbeiten | Wand | Außenwand 7-Schalig | WA-HD |  |  | 0 |  | NEW |  |  | 0 | AllplanAttributes - Ortscode_Geschoßbezeichnung: E00; ash D_Detailverweis: DT D; ash D_Plannummer: D1851; Sicherheitsklasse: -
 | H2 Ebene 0 | WA-DL | 1105Wa 2005677952 | yes |  | m³ | Zimmer- und Holzbauarbeiten | Wand | Außenwand 7-Schalig | WA-DL |  |  | 0 |  | NEW |  |  | 0 | AllplanAttributes - Ortscode_Geschoßbezeichnung: E00; Sicherheitsklasse: -
 | H2 Ebene 0 | WA-LB | 1105Wa 2005677953 | yes |  | m² | Trockenbauarbeiten | Wand | Außenwand 7-Schalig | WA-LB |  |  | 0 |  | NEW |  |  | 0 | AllplanAttributes - Ortscode_Geschoßbezeichnung: E00; Sicherheitsklasse: -
 | H2 Ebene 0 | WI-GKF | 1105Wa 0811656630 |  |  | m² | Trockenbauarbeiten | Wand | """""""BS-Beplankung; 2-fach Gipsfaserplatten""""""" | WI-GKF |  |  | 0 | AllplanAttributes - Sicherheitsklasse: -
 | H2 Ebene 0 | WI-GKF | 1105Wa 0811657685 |  |  | m² | Trockenbauarbeiten | Wand | """""""BS-Beplankung; 2-fach Gipsfaserplatten""""""" | WI-GKF |  |  | 0 | AllplanAttributes - Sicherheitsklasse: -
 | H2 Ebene 0 | WI-GKF | 1105Wa 0811657999 |  |  | m² | Trockenbauarbeiten | Wand | """""""BS-Beplankung; 2-fach Gipsfaserplatten""""""" | WI-GKF |  |  | 0 | AllplanAttributes - Sicherheitsklasse: -
 | H2 Ebene 0 | WI-GKF | 1105Wa 0811657715 |  |  | m² | Trockenbauarbeiten | Wand | """""""BS-Beplankung; 2-fach Gipsfaserplatten""""""" | WI-GKF |  |  | 0 | AllplanAttributes - Sicherheitsklasse: -
 | H2 Ebene 0 | WA-LB | 1105Wa 0811567724 | yes |  | m² | Trockenbauarbeiten | Wand | Außenwand 7-Schalig | WA-LB |  |  | 0 |  | NEW |  |  | 0 | AllplanAttributes - Ortscode_Geschoßbezeichnung: E00; Sicherheitsklasse: -
 | H2 Ebene 0 | WA-LB | 1105Wa 0811567725 | yes |  | m³ | Trockenbauarbeiten | Wand | Außenwand 7-Schalig | WA-LB |  |  | 0 |  | NEW |  |  | 0 | AllplanAttributes - Ortscode_Geschoßbezeichnung: E00; Sicherheitsklasse: -
 | H2 Ebene 0 | WA-HD | 1105Wa 0811567726 | yes |  | m³ | Zimmer- und Holzbauarbeiten | Wand | Außenwand 7-Schalig | WA-HD |  |  | 0 |  | NEW |  |  | 0 | AllplanAttributes - Ortscode_Geschoßbezeichnung: E00; ash D_Detailverweis: DT A; ash D_Plannummer: D1850; Sicherheitsklasse: -
 | H2 Ebene 0 | WA-LB | 1105Wa 0811567722 | yes |  | m³ | Trockenbauarbeiten | Wand | Außenwand 7-Schalig | WA-LB |  |  | 0 |  | NEW |  |  | 0 | AllplanAttributes - Ortscode_Geschoßbezeichnung: E00; Sicherheitsklasse: -
 | H2 Ebene 0 | WA-TP | 1105Wa 0811567721 | yes |  | m² | Trockenbauarbeiten | Wand | Außenwand 7-Schalig | WA-TP |  |  | 0 |  | NEW |  |  | 0 | AllplanAttributes - Ortscode_Geschoßbezeichnung: E00; Sicherheitsklasse: -
 | H2 Ebene 0 | WA-DL | 1105Wa 0811567720 | yes |  | m³ | Zimmer- und Holzbauarbeiten | Wand | Außenwand 7-Schalig | WA-DL |  |  | 0 |  | NEW |  |  | 0 | AllplanAttributes - Ortscode_Geschoßbezeichnung: E00; Sicherheitsklasse: -
 | H2 Ebene 0 | WA-KL | 1105Wa 0811567719 | yes |  | m² | Zimmer- und Holzbauarbeiten | Wand | Außenwand 7-Schalig | WA-KL |  |  | 0 |  | NEW |  |  | 0 | AllplanAttributes - Ortscode_Geschoßbezeichnung: E00; Sicherheitsklasse: -
 | H2 Ebene 0 | WA-TL | 1105Wa 0811567718 | yes |  | m² | Zimmer- und Holzbauarbeiten | Wand | Außenwand 7-Schalig | WA-TL |  |  | 0 |  | NEW |  |  | 0 | AllplanAttributes - Ortscode_Geschoßbezeichnung: E00; Sicherheitsklasse: -
 | H2 Ebene 0 | WA-HS | 1105Wa 0811567717 | yes |  | m² | Zimmer- und Holzbauarbeiten | Wand | Außenwand 7-Schalig | WA-HS |  |  | 0 |  | NEW |  |  | 0 | AllplanAttributes - Ortscode_Geschoßbezeichnung: E00; Sicherheitsklasse: -
 | H2 Ebene 0 | WA-LB | 1105Wa 0811642214 | yes |  | m² | Trockenbauarbeiten | Wand | Außenwand 7-Schalig | WA-LB |  |  | 0 |  | NEW |  |  | 0 | AllplanAttributes - Ortscode_Geschoßbezeichnung: E00; Sicherheitsklasse: -
 | H2 Ebene 0 | WA-LB | 1105Wa 0811642212 | yes |  | m³ | Trockenbauarbeiten | Wand | Außenwand 7-Schalig | WA-LB |  |  | 0 |  | NEW |  |  | 0 | AllplanAttributes - Ortscode_Geschoßbezeichnung: E00; Sicherheitsklasse: -
 | H2 Ebene 0 | WA-HD | 1105Wa 0811642215 | yes |  | m³ | Zimmer- und Holzbauarbeiten | Wand | Außenwand 7-Schalig | WA-HD |  |  | 0 |  | NEW |  |  | 0 | AllplanAttributes - Ortscode_Geschoßbezeichnung: E00; Sicherheitsklasse: -
 | H2 Ebene 0 | WA-LB | 1105Wa 0811642219 | yes |  | m³ | Trockenbauarbeiten | Wand | Außenwand 7-Schalig | WA-LB |  |  | 0 |  | NEW |  |  | 0 | AllplanAttributes - Ortscode_Geschoßbezeichnung: E00; Sicherheitsklasse: -
 | H2 Ebene 0 | WA-TP | 1105Wa 0811642218 | yes |  | m² | Trockenbauarbeiten | Wand | Außenwand 7-Schalig | WA-TP |  |  | 0 |  | NEW |  |  | 0 | AllplanAttributes - Ortscode_Geschoßbezeichnung: E00; Sicherheitsklasse: -
 | H2 Ebene 0 | WA-DL | 1105Wa 0811642216 | yes |  | m³ | Zimmer- und Holzbauarbeiten | Wand | Außenwand 7-Schalig | WA-DL |  |  | 0 |  | NEW |  |  | 0 | AllplanAttributes - Ortscode_Geschoßbezeichnung: E00; Sicherheitsklasse: -
 | H2 Ebene 0 | WA-KL | 1105Wa 0811642213 | yes |  | m² | Zimmer- und Holzbauarbeiten | Wand | Außenwand 7-Schalig | WA-KL |  |  | 0 |  | NEW |  |  | 0 | AllplanAttributes - Ortscode_Geschoßbezeichnung: E00; Sicherheitsklasse: -
 | H2 Ebene 0 | WA-TL | 1105Wa 0811642217 | yes |  | m² | Zimmer- und Holzbauarbeiten | Wand | Außenwand 7-Schalig | WA-TL |  |  | 0 |  | NEW |  |  | 0 | AllplanAttributes - Ortscode_Geschoßbezeichnung: E00; Sicherheitsklasse: -
 | H2 Ebene 0 | WA-HS | 1105Wa 0811642220 | yes |  | m² | Zimmer- und Holzbauarbeiten | Wand | Außenwand 7-Schalig | WA-HS |  |  | 0 |  | NEW |  |  | 0 | AllplanAttributes - Ortscode_Geschoßbezeichnung: E00; Sicherheitsklasse: -
 | H2 Ebene 0 | WA-LB | 1105Wa 0000004356 | yes |  | m² | Trockenbauarbeiten | Wand | Außenwand 7-Schalig | WA-LB |  |  | 0 |  | NEW |  |  | 0 | AllplanAttributes - Ortscode_Geschoßbezeichnung: E00; Sicherheitsklasse: -
 | H2 Ebene 0 | WA-LB | 1105Wa 0000004360 | yes |  | m³ | Trockenbauarbeiten | Wand | Außenwand 7-Schalig | WA-LB |  |  | 0 |  | NEW |  |  | 0 | AllplanAttributes - Ortscode_Geschoßbezeichnung: E00; Sicherheitsklasse: -
 | H2 Ebene 0 | WA-HD | 1105Wa 0000004364 | yes |  | m³ | Zimmer- und Holzbauarbeiten | Wand | Außenwand 7-Schalig | WA-HD |  |  | 0 |  | NEW |  |  | 0 | AllplanAttributes - Ortscode_Geschoßbezeichnung: E00; Sicherheitsklasse: -
 | H2 Ebene 0 | WA-LB | 1105Wa 0000004368 | yes |  | m³ | Trockenbauarbeiten | Wand | Außenwand 7-Schalig | WA-LB |  |  | 0 |  | NEW |  |  | 0 | AllplanAttributes - Ortscode_Geschoßbezeichnung: E00; Sicherheitsklasse: -
 | H2 Ebene 0 | WA-LB | 1105Wa 0000004372 | yes |  | m² | Trockenbauarbeiten | Wand | Außenwand 7-Schalig | WA-LB |  |  | 0 |  | NEW |  |  | 0 | AllplanAttributes - Ortscode_Geschoßbezeichnung: E00; Sicherheitsklasse: -
 | H2 Ebene 0 | WA-DL | 1105Wa 0000004376 | yes |  | m³ | Zimmer- und Holzbauarbeiten | Wand | Außenwand 7-Schalig | WA-DL |  |  | 0 |  | NEW |  |  | 0 | AllplanAttributes - Ortscode_Geschoßbezeichnung: E00; Sicherheitsklasse: -
 | H2 Ebene 0 | WA-KL | 1105Wa 0000004380 | yes |  | m² | Zimmer- und Holzbauarbeiten | Wand | Außenwand 7-Schalig | WA-KL |  |  | 0 |  | NEW |  |  | 0 | AllplanAttributes - Ortscode_Geschoßbezeichnung: E00; Sicherheitsklasse: -
 | H2 Ebene 0 | WA-TL | 1105Wa 0811441768 | yes |  | m² | Zimmer- und Holzbauarbeiten | Wand | Außenwand 7-Schalig | WA-TL |  |  | 0 |  | NEW |  |  | 0 | AllplanAttributes - Ortscode_Geschoßbezeichnung: E00; Sicherheitsklasse: -
 | H2 Ebene 0 | WA-HS | 1105Wa 0811451476 | yes |  | m² | Zimmer- und Holzbauarbeiten | Wand | Außenwand 7-Schalig | WA-HS |  |  | 0 |  | NEW |  |  | 0 | AllplanAttributes - Ortscode_Geschoßbezeichnung: E00; Sicherheitsklasse: -
 | H2 Ebene 0 | WA-LB | 1105Wa 0000004352 | yes |  | m² | Trockenbauarbeiten | Wand | Außenwand 7-Schalig | WA-LB |  |  | 0 |  | NEW |  |  | 0 | AllplanAttributes - Ortscode_Geschoßbezeichnung: E00; Sicherheitsklasse: -
 | H2 Ebene 0 | WA-HD | 1105Wa 0000004350 | yes |  | m³ | Zimmer- und Holzbauarbeiten | Wand | Außenwand 7-Schalig | WA-HD |  |  | 0 |  | NEW |  |  | 0 | AllplanAttributes - Ortscode_Geschoßbezeichnung: E00; Sicherheitsklasse: -
 | H2 Ebene 0 | WA-DL | 1105Wa 0000004348 | yes |  | m³ | Zimmer- und Holzbauarbeiten | Wand | Außenwand 7-Schalig | WA-DL |  |  | 0 |  | NEW |  |  | 0 | AllplanAttributes - Ortscode_Geschoßbezeichnung: E00; Sicherheitsklasse: -
 | H2 Ebene 0 | WA-TP | 1105Wa 0000004346 | yes |  | m² | Trockenbauarbeiten | Wand | Außenwand 7-Schalig | WA-TP |  |  | 0 |  | NEW |  |  | 0 | AllplanAttributes - Ortscode_Geschoßbezeichnung: E00; Sicherheitsklasse: -
 | H2 Ebene 0 | WA-KL | 1105Wa 0000004344 | yes |  | m² | Zimmer- und Holzbauarbeiten | Wand | Außenwand 7-Schalig | WA-KL |  |  | 0 |  | NEW |  |  | 0 | AllplanAttributes - Ortscode_Geschoßbezeichnung: E00; Sicherheitsklasse: -
 | H2 Ebene 0 | WA-TL | 1105Wa 0000004342 | yes |  | m² | Zimmer- und Holzbauarbeiten | Wand | Außenwand 7-Schalig | WA-TL |  |  | 0 |  | NEW |  |  | 0 | AllplanAttributes - Ortscode_Geschoßbezeichnung: E00; Sicherheitsklasse: -
 | H2 Ebene 0 | WA-HS | 1105Wa 0000004340 | yes |  | m² | Zimmer- und Holzbauarbeiten | Wand | Außenwand 7-Schalig | WA-HS |  |  | 0 |  | NEW |  |  | 0 | AllplanAttributes - Ortscode_Geschoßbezeichnung: E00; Sicherheitsklasse: -
 | H2 Ebene 0 | WA-LB | 1105Wa 0000000332 | yes |  | m² | Trockenbauarbeiten | Wand | Außenwand 7-Schalig | WA-LB |  |  | 0 |  | NEW |  |  | 0 | AllplanAttributes - Ortscode_Geschoßbezeichnung: E00; Sicherheitsklasse: -
 | H2 Ebene 0 | WA-HD | 1105Wa 0000000336 | yes |  | m³ | Zimmer- und Holzbauarbeiten | Wand | Außenwand 7-Schalig | WA-HD |  |  | 0 |  | NEW |  |  | 0 | AllplanAttributes - Ortscode_Geschoßbezeichnung: E00; Sicherheitsklasse: -
 | H2 Ebene 0 | WA-DL | 1105Wa 0000000356 | yes |  | m³ | Zimmer- und Holzbauarbeiten | Wand | Außenwand 7-Schalig | WA-DL |  |  | 0 |  | NEW |  |  | 0 | AllplanAttributes - Ortscode_Geschoßbezeichnung: E00; Sicherheitsklasse: -
 | H2 Ebene 0 | WA-TP | 1105Wa 0000000352 | yes |  | m² | Zimmer- und Holzbauarbeiten | Wand | Außenwand 7-Schalig | WA-TP |  |  | 0 |  | NEW |  |  | 0 | AllplanAttributes - Ortscode_Geschoßbezeichnung: E00; Sicherheitsklasse: -
 | H2 Ebene 0 | WA-KL | 1105Wa 0000000348 | yes |  | m² | Zimmer- und Holzbauarbeiten | Wand | Außenwand 7-Schalig | WA-KL |  |  | 0 |  | NEW |  |  | 0 | AllplanAttributes - Ortscode_Geschoßbezeichnung: E00; Sicherheitsklasse: -
 | H2 Ebene 0 | WA-TL | 1105Wa 0000000344 | yes |  | m² | Zimmer- und Holzbauarbeiten | Wand | Außenwand 7-Schalig | WA-TL |  |  | 0 |  | NEW |  |  | 0 | AllplanAttributes - Ortscode_Geschoßbezeichnung: E00; Sicherheitsklasse: -
 | H2 Ebene 0 | WA-HS | 1105Wa 0000000340 | yes |  | m² | Zimmer- und Holzbauarbeiten | Wand | Außenwand 7-Schalig | WA-HS |  |  | 0 |  | NEW |  |  | 0 | AllplanAttributes - Ortscode_Geschoßbezeichnung: E00; Sicherheitsklasse: -
 | H2 Ebene 0 | WA-LB | 1105Wa 0811560456 | yes |  | m² | Trockenbauarbeiten | Wand | Außenwand 7-Schalig | WA-LB |  |  | 0 |  | NEW |  |  | 0 | AllplanAttributes - Ortscode_Geschoßbezeichnung: E00; ash_W_Trockenbau_Qualitäten: 6; Sicherheitsklasse: -
 | H2 Ebene 0 | WA-LB | 1105Wa 0811560455 | yes |  | m³ | Trockenbauarbeiten | Wand | Außenwand 7-Schalig | WA-LB |  |  | 0 |  | NEW |  |  | 0 | AllplanAttributes - Ortscode_Geschoßbezeichnung: E00; Sicherheitsklasse: -
 | H2 Ebene 0 | WA-HD | 1105Wa 0811560454 | yes |  | m³ | Zimmer- und Holzbauarbeiten | Wand | Außenwand 7-Schalig | WA-HD |  |  | 0 |  | NEW |  |  | 0 | AllplanAttributes - Ortscode_Geschoßbezeichnung: E00; ash D_Detailverweis: DT F; ash D_Plannummer: D1851; Sicherheitsklasse: -
 | H2 Ebene 0 | WA-LB | 1105Wa 0811560453 | yes |  | m³ | Trockenbauarbeiten | Wand | Außenwand 7-Schalig | WA-LB |  |  | 0 |  | NEW |  |  | 0 | AllplanAttributes - Ortscode_Geschoßbezeichnung: E00; Sicherheitsklasse: -
 | H2 Ebene 0 | WA-TP | 1105Wa 0811560452 | yes |  | m² | Trockenbauarbeiten | Wand | Außenwand 7-Schalig | WA-TP |  |  | 0 |  | NEW |  |  | 0 | AllplanAttributes - Ortscode_Geschoßbezeichnung: E00; Sicherheitsklasse: -
 | H2 Ebene 0 | WA-DL | 1105Wa 0811560451 | yes |  | m³ | Zimmer- und Holzbauarbeiten | Wand | Außenwand 7-Schalig | WA-DL |  |  | 0 |  | NEW |  |  | 0 | AllplanAttributes - Ortscode_Geschoßbezeichnung: E00; Sicherheitsklasse: -
 | H2 Ebene 0 | WA-KL | 1105Wa 0811560450 | yes |  | m² | Zimmer- und Holzbauarbeiten | Wand | Außenwand 7-Schalig | WA-KL |  |  | 0 |  | NEW |  |  | 0 | AllplanAttributes - Ortscode_Geschoßbezeichnung: E00; Sicherheitsklasse: -
 | H2 Ebene 0 | WA-TL | 1105Wa 0811560449 | yes |  | m² | Zimmer- und Holzbauarbeiten | Wand | Außenwand 7-Schalig | WA-TL |  |  | 0 |  | NEW |  |  | 0 | AllplanAttributes - Ortscode_Geschoßbezeichnung: E00; Sicherheitsklasse: -
 | H2 Ebene 0 | WA-HS | 1105Wa 0811560448 | yes |  | m² | Zimmer- und Holzbauarbeiten | Wand | Außenwand 7-Schalig | WA-HS |  |  | 0 |  | NEW |  |  | 0 | AllplanAttributes - Ortscode_Geschoßbezeichnung: E00; ash D_Detailverweis: FS12; ash D_Plannummer: D1854; Sicherheitsklasse: -
 | H2 Ebene 0 | WA-LB | 1105Wa 2005764973 | yes |  | m² | Trockenbauarbeiten | Wand | Außenwand 7-Schalig | WA-LB |  |  | 0 |  | NEW |  |  | 0 | AllplanAttributes - Ortscode_Geschoßbezeichnung: E00; Sicherheitsklasse: -
 | H2 Ebene 0 | WA-LB | 1105Wa 2005764974 | yes |  | m² | Trockenbauarbeiten | Wand | Außenwand 7-Schalig | WA-LB |  |  | 0 |  | NEW |  |  | 0 | AllplanAttributes - Ortscode_Geschoßbezeichnung: E00; Sicherheitsklasse: -
 | H2 Ebene 0 | WA-HD | 1105Wa 2005764975 | yes |  | m³ | Zimmer- und Holzbauarbeiten | Wand | Außenwand 7-Schalig | WA-HD |  |  | 0 |  | NEW |  |  | 0 | AllplanAttributes - Ortscode_Geschoßbezeichnung: E00; ash D_Detailverweis: DT D; ash D_Plannummer: D1851; Sicherheitsklasse: -
 | H2 Ebene 0 | WA-DL | 1105Wa 2005764976 | yes |  | m³ | Zimmer- und Holzbauarbeiten | Wand | Außenwand 7-Schalig | WA-DL |  |  | 0 |  | NEW |  |  | 0 | AllplanAttributes - Ortscode_Geschoßbezeichnung: E00; Sicherheitsklasse: -
 | H2 Ebene 0 | WA-LB | 1105Wa 2005764977 | yes |  | m² | Trockenbauarbeiten | Wand | Außenwand 7-Schalig | WA-LB |  |  | 0 |  | NEW |  |  | 0 | AllplanAttributes - Ortscode_Geschoßbezeichnung: E00; Sicherheitsklasse: -
 | H2 Ebene 0 | WA-LB | 1105Wa 0000180626 |  |  | m² | Trockenbauarbeiten | Wand | Außenwand 7-Schalig | WA-LB |  |  | 0 |  |  |  |  | 0 | AllplanAttributes - Ortscode_Geschoßbezeichnung: E00; Sicherheitsklasse: -
 | H2 Ebene 0 | WA-HD | 1105Wa 0000180627 |  |  | m³ | Zimmer- und Holzbauarbeiten | Wand | Außenwand 7-Schalig | WA-HD |  |  | 0 |  |  |  |  | 0 | AllplanAttributes - Ortscode_Geschoßbezeichnung: E00; Sicherheitsklasse: -
 | H2 Ebene 0 | WA-DL | 1105Wa 0000180628 |  |  | m³ | Zimmer- und Holzbauarbeiten | Wand | Außenwand 7-Schalig | WA-DL |  |  | 0 |  |  |  |  | 0 | AllplanAttributes - Ortscode_Geschoßbezeichnung: E00; Sicherheitsklasse: -
 | H2 Ebene 0 | WA-DL | 1105Wa 0000180629 |  |  | m³ | Zimmer- und Holzbauarbeiten | Wand | Außenwand 7-Schalig | WA-DL |  |  | 0 |  |  |  |  | 0 | AllplanAttributes - Ortscode_Geschoßbezeichnung: E00; Sicherheitsklasse: -
 | H2 Ebene 0 | WA-LB | 1105Wa 0000180630 |  |  | m² | Trockenbauarbeiten | Wand | Außenwand 7-Schalig | WA-LB |  |  | 0 |  |  |  |  | 0 | AllplanAttributes - Ortscode_Geschoßbezeichnung: E00; Sicherheitsklasse: -
 | H2 Ebene 0 | WA-KL | 1105Wa 0000180631 |  |  | m² | Zimmer- und Holzbauarbeiten | Wand | Außenwand 7-Schalig | WA-KL |  |  | 0 |  |  |  |  | 0 | AllplanAttributes - Ortscode_Geschoßbezeichnung: E00; Sicherheitsklasse: -
 | H2 Ebene 0 | WA-TL | 1105Wa 0000180632 |  |  | m² | Zimmer- und Holzbauarbeiten | Wand | Außenwand 7-Schalig | WA-TL |  |  | 0 |  |  |  |  | 0 | AllplanAttributes - Ortscode_Geschoßbezeichnung: E00; Sicherheitsklasse: -
 | H2 Ebene 0 | WA-HS | 1105Wa 0811580073 |  |  | m² | Zimmer- und Holzbauarbeiten | Wand | Außenwand 7-Schalig | WA-HS |  |  | 0 |  |  |  |  | 0 | AllplanAttributes - Ortscode_Geschoßbezeichnung: E00; Sicherheitsklasse: -
 | H2 Ebene 0 | WA-LB | 1105Wa 0000001663 | yes |  | m² | Trockenbauarbeiten | Wand | Außenwand 7-Schalig | WA-LB |  |  | 0 |  | NEW |  |  | 0 | AllplanAttributes - Ortscode_Geschoßbezeichnung: E00; Sicherheitsklasse: -
 | H2 Ebene 0 | WA-HD | 1105Wa 0000001665 | yes |  | m³ | Zimmer- und Holzbauarbeiten | Wand | Außenwand 7-Schalig | WA-HD |  |  | 0 |  | NEW |  |  | 0 | AllplanAttributes - Ortscode_Geschoßbezeichnung: E00; ash D_Detailverweis: DT H; ash D_Plannummer: D1853; Sicherheitsklasse: -
 | H2 Ebene 0 | WA-DL | 1105Wa 0000001667 | yes |  | m³ | Zimmer- und Holzbauarbeiten | Wand | Außenwand 7-Schalig | WA-DL |  |  | 0 |  | NEW |  |  | 0 | AllplanAttributes - Ortscode_Geschoßbezeichnung: E00; Sicherheitsklasse: -
 | H2 Ebene 0 | WA-TP | 1105Wa 0000001669 | yes |  | m² | Zimmer- und Holzbauarbeiten | Wand | Außenwand 7-Schalig | WA-TP |  |  | 0 |  | NEW |  |  | 0 | AllplanAttributes - Ortscode_Geschoßbezeichnung: E00; Sicherheitsklasse: -
 | H2 Ebene 0 | WA-KL | 1105Wa 0000001671 | yes |  | m² | Zimmer- und Holzbauarbeiten | Wand | Außenwand 7-Schalig | WA-KL |  |  | 0 |  | NEW |  |  | 0 | AllplanAttributes - Ortscode_Geschoßbezeichnung: E00; Sicherheitsklasse: -
 | H2 Ebene 0 | WA-TL | 1105Wa 0000001673 | yes |  | m² | Zimmer- und Holzbauarbeiten | Wand | Außenwand 7-Schalig | WA-TL |  |  | 0 |  | NEW |  |  | 0 | AllplanAttributes - Ortscode_Geschoßbezeichnung: E00; Sicherheitsklasse: -
 | H2 Ebene 0 | WA-HS | 1105Wa 0811632869 | yes |  | m² | Zimmer- und Holzbauarbeiten | Wand | Außenwand 7-Schalig | WA-HS |  |  | 0 |  | NEW |  |  | 0 | AllplanAttributes - Ortscode_Geschoßbezeichnung: E00; Sicherheitsklasse: -
 | H2 Ebene 0 | WA-LB | 1105Wa 0811650022 | yes |  | m² | Trockenbauarbeiten | Wand | Außenwand 7-Schalig | WA-LB |  |  | 0 |  | NEW | no |  | 0 | AllplanAttributes - Ortscode_Geschoßbezeichnung: E00; Sicherheitsklasse: -
 | H2 Ebene 0 | WA-HD | 1105Wa 0811650021 | yes |  | m³ | Zimmer- und Holzbauarbeiten | Wand | Außenwand 7-Schalig | WA-HD |  |  | 0 |  | NEW | no |  | 0 | AllplanAttributes - Ortscode_Geschoßbezeichnung: E00; Sicherheitsklasse: -
 | H2 Ebene 0 | WA-DL | 1105Wa 0811650019 | yes |  | m³ | Zimmer- und Holzbauarbeiten | Wand | Außenwand 7-Schalig | WA-DL |  |  | 0 |  | NEW | no |  | 0 | AllplanAttributes - Ortscode_Geschoßbezeichnung: E00; Sicherheitsklasse: -
 | H2 Ebene 0 | WA-TP | 1105Wa 0811650018 | yes |  | m² | Zimmer- und Holzbauarbeiten | Wand | Außenwand 7-Schalig | WA-TP |  |  | 0 |  | NEW | no |  | 0 | AllplanAttributes - Ortscode_Geschoßbezeichnung: E00; Sicherheitsklasse: -
 | H2 Ebene 0 | WA-KL | 1105Wa 0811650016 | yes |  | m² | Zimmer- und Holzbauarbeiten | Wand | Außenwand 7-Schalig | WA-KL |  |  | 0 |  | NEW | no |  | 0 | AllplanAttributes - Ortscode_Geschoßbezeichnung: E00; Sicherheitsklasse: -
 | H2 Ebene 0 | WA-TL | 1105Wa 0811650017 | yes |  | m² | Zimmer- und Holzbauarbeiten | Wand | Außenwand 7-Schalig | WA-TL |  |  | 0 |  | NEW | no |  | 0 | AllplanAttributes - Ortscode_Geschoßbezeichnung: E00; Sicherheitsklasse: -
 | H2 Ebene 0 | WA-HS | 1105Wa 0811650020 | yes |  | m² | Zimmer- und Holzbauarbeiten | Wand | Außenwand 7-Schalig | WA-HS |  |  | 0 |  | NEW | no |  | 0 | AllplanAttributes - Ortscode_Geschoßbezeichnung: E00; Sicherheitsklasse: -
 | H2 Ebene 0 | WA-LB | 1105Wa 0000003877 | yes |  | m² | Trockenbauarbeiten | Wand | Außenwand 7-Schalig | WA-LB |  |  | 0 |  | NEW |  |  | 0 | AllplanAttributes - Ortscode_Geschoßbezeichnung: E00; Sicherheitsklasse: -
 | H2 Ebene 0 | WA-HD | 1105Wa 0000003882 | yes |  | m³ | Zimmer- und Holzbauarbeiten | Wand | Außenwand 7-Schalig | WA-HD |  |  | 0 |  | NEW |  |  | 0 | AllplanAttributes - Ortscode_Geschoßbezeichnung: E00; Sicherheitsklasse: -
 | H2 Ebene 0 | WA-DL | 1105Wa 0000003886 | yes |  | m³ | Zimmer- und Holzbauarbeiten | Wand | Außenwand 7-Schalig | WA-DL |  |  | 0 |  | NEW |  |  | 0 | AllplanAttributes - Ortscode_Geschoßbezeichnung: E00; Sicherheitsklasse: -
 | H2 Ebene 0 | WA-DL | 1105Wa 0000003891 | yes |  | m³ | Zimmer- und Holzbauarbeiten | Wand | Außenwand 7-Schalig | WA-DL |  |  | 0 |  | NEW |  |  | 0 | AllplanAttributes - Ortscode_Geschoßbezeichnung: E00; Sicherheitsklasse: -
 | H2 Ebene 0 | WA-LB | 1105Wa 0000003896 | yes |  | m² | Trockenbauarbeiten | Wand | Außenwand 7-Schalig | WA-LB |  |  | 0 |  | NEW |  |  | 0 | AllplanAttributes - Ortscode_Geschoßbezeichnung: E00; Sicherheitsklasse: -
 | H2 Ebene 0 | WA-KL | 1105Wa 0000003901 | yes |  | m² | Zimmer- und Holzbauarbeiten | Wand | Außenwand 7-Schalig | WA-KL |  |  | 0 |  | NEW |  |  | 0 | AllplanAttributes - Ortscode_Geschoßbezeichnung: E00; Sicherheitsklasse: -
 | H2 Ebene 0 | WA-TL | 1105Wa 0000003906 | yes |  | m² | Zimmer- und Holzbauarbeiten | Wand | Außenwand 7-Schalig | WA-TL |  |  | 0 |  | NEW |  |  | 0 | AllplanAttributes - Ortscode_Geschoßbezeichnung: E00; Sicherheitsklasse: -
 | H2 Ebene 0 | WA-HS | 1105Wa 0811578750 | yes |  | m² | Zimmer- und Holzbauarbeiten | Wand | Außenwand 7-Schalig | WA-HS |  |  | 0 |  | NEW |  |  | 0 | AllplanAttributes - Ortscode_Geschoßbezeichnung: E00; Sicherheitsklasse: -
 | H2 Ebene 0 | WA-LB | 1105Wa 0000001868 | yes |  | m² | Trockenbauarbeiten | Wand | Außenwand 7-Schalig | WA-LB |  |  | 0 |  | NEW |  |  | 0 | AllplanAttributes - Ortscode_Geschoßbezeichnung: E00; Sicherheitsklasse: -
 | H2 Ebene 0 | WA-HD | 1105Wa 0000001872 | yes |  | m³ | Zimmer- und Holzbauarbeiten | Wand | Außenwand 7-Schalig | WA-HD |  |  | 0 |  | NEW |  |  | 0 | AllplanAttributes - Ortscode_Geschoßbezeichnung: E00; ash D_Detailverweis: DT C; ash D_Plannummer: D1851; Sicherheitsklasse: -
 | H2 Ebene 0 | WA-DL | 1105Wa 0000001876 | yes |  | m³ | Zimmer- und Holzbauarbeiten | Wand | Außenwand 7-Schalig | WA-DL |  |  | 0 |  | NEW |  |  | 0 | AllplanAttributes - Ortscode_Geschoßbezeichnung: E00; Sicherheitsklasse: -
 | H2 Ebene 0 | WA-TP | 1105Wa 0000001880 | yes |  | m² | Zimmer- und Holzbauarbeiten | Wand | Außenwand 7-Schalig | WA-TP |  |  | 0 |  | NEW |  |  | 0 | AllplanAttributes - Ortscode_Geschoßbezeichnung: E00; Sicherheitsklasse: -
 | H2 Ebene 0 | WA-KL | 1105Wa 0000001884 | yes |  | m² | Zimmer- und Holzbauarbeiten | Wand | Außenwand 7-Schalig | WA-KL |  |  | 0 |  | NEW |  |  | 0 | AllplanAttributes - Ortscode_Geschoßbezeichnung: E00; Sicherheitsklasse: -
 | H2 Ebene 0 | WA-TL | 1105Wa 0000001888 | yes |  | m² | Zimmer- und Holzbauarbeiten | Wand | Außenwand 7-Schalig | WA-TL |  |  | 0 |  | NEW |  |  | 0 | AllplanAttributes - Ortscode_Geschoßbezeichnung: E00; Sicherheitsklasse: -
 | H2 Ebene 0 | WA-HS | 1105Wa 0000001892 | yes |  | m² | Zimmer- und Holzbauarbeiten | Wand | Außenwand 7-Schalig | WA-HS |  |  | 0 |  | NEW |  |  | 0 | AllplanAttributes - Ortscode_Geschoßbezeichnung: E00; Sicherheitsklasse: -
 | H2 Ebene 0 | WA-LB | 1105Wa 0811559664 | yes |  | m² | Trockenbauarbeiten | Wand | Außenwand 7-Schalig | WA-LB |  |  | 0 |  | NEW |  |  | 0 | AllplanAttributes - Ortscode_Geschoßbezeichnung: E00; Sicherheitsklasse: -
 | H2 Ebene 0 | WA-HD | 1105Wa 0811559663 | yes |  | m³ | Zimmer- und Holzbauarbeiten | Wand | Außenwand 7-Schalig | WA-HD |  |  | 0 |  | NEW |  |  | 0 | AllplanAttributes - Ortscode_Geschoßbezeichnung: E00; ash D_Detailverweis: DT F; ash D_Plannummer: D1851; Sicherheitsklasse: -
 | H2 Ebene 0 | WA-DL | 1105Wa 0811559662 | yes |  | m³ | Zimmer- und Holzbauarbeiten | Wand | Außenwand 7-Schalig | WA-DL |  |  | 0 |  | NEW |  |  | 0 | AllplanAttributes - Ortscode_Geschoßbezeichnung: E00; Sicherheitsklasse: -
 | H2 Ebene 0 | WA-TP | 1105Wa 0811559661 | yes |  | m² | Zimmer- und Holzbauarbeiten | Wand | Außenwand 7-Schalig | WA-TP |  |  | 0 |  | NEW |  |  | 0 | AllplanAttributes - Ortscode_Geschoßbezeichnung: E00; Sicherheitsklasse: -
 | H2 Ebene 0 | WA-KL | 1105Wa 0811559660 | yes |  | m² | Zimmer- und Holzbauarbeiten | Wand | Außenwand 7-Schalig | WA-KL |  |  | 0 |  | NEW |  |  | 0 | AllplanAttributes - Ortscode_Geschoßbezeichnung: E00; Sicherheitsklasse: -
 | H2 Ebene 0 | WA-TL | 1105Wa 0811559659 | yes |  | m² | Zimmer- und Holzbauarbeiten | Wand | Außenwand 7-Schalig | WA-TL |  |  | 0 |  | NEW |  |  | 0 | AllplanAttributes - Ortscode_Geschoßbezeichnung: E00; Sicherheitsklasse: -
 | H2 Ebene 0 | WA-HS | 1105Wa 0811559658 | yes |  | m² | Zimmer- und Holzbauarbeiten | Wand | Außenwand 7-Schalig | WA-HS |  |  | 0 |  | NEW |  |  | 0 | AllplanAttributes - Ortscode_Geschoßbezeichnung: E00; ash D_Detailverweis: FS13; ash D_Plannummer: D1854; Sicherheitsklasse: -
 | H2 Ebene 0 | WA-LB | 1105Wa 0811564781 | yes |  | m² | Trockenbauarbeiten | Wand | Außenwand 7-Schalig | WA-LB |  |  | 0 |  | NEW |  |  | 0 | AllplanAttributes - Ortscode_Geschoßbezeichnung: E00; Sicherheitsklasse: -
 | H2 Ebene 0 | WA-LB | 1105Wa 0811564780 | yes |  | m³ | Trockenbauarbeiten | Wand | Außenwand 7-Schalig | WA-LB |  |  | 0 |  | NEW |  |  | 0 | AllplanAttributes - Ortscode_Geschoßbezeichnung: E00; Sicherheitsklasse: -
 | H2 Ebene 0 | WA-HD | 1105Wa 0811564779 | yes |  | m³ | Zimmer- und Holzbauarbeiten | Wand | Außenwand 7-Schalig | WA-HD |  |  | 0 |  | NEW |  |  | 0 | AllplanAttributes - Ortscode_Geschoßbezeichnung: E00; ash D_Detailverweis: DT A; ash D_Plannummer: D1850; Sicherheitsklasse: -
 | H2 Ebene 0 | WA-LB | 1105Wa 0811564778 | yes |  | m³ | Trockenbauarbeiten | Wand | Außenwand 7-Schalig | WA-LB |  |  | 0 |  | NEW |  |  | 0 | AllplanAttributes - Ortscode_Geschoßbezeichnung: E00; Sicherheitsklasse: -
 | H2 Ebene 0 | WA-TP | 1105Wa 0811564777 | yes |  | m² | Trockenbauarbeiten | Wand | Außenwand 7-Schalig | WA-TP |  |  | 0 |  | NEW |  |  | 0 | AllplanAttributes - Ortscode_Geschoßbezeichnung: E00; Sicherheitsklasse: -
 | H2 Ebene 0 | WA-DL | 1105Wa 0811564776 | yes |  | m³ | Zimmer- und Holzbauarbeiten | Wand | Außenwand 7-Schalig | WA-DL |  |  | 0 |  | NEW |  |  | 0 | AllplanAttributes - Ortscode_Geschoßbezeichnung: E00; Sicherheitsklasse: -
 | H2 Ebene 0 | WA-KL | 1105Wa 0811564775 | yes |  | m² | Zimmer- und Holzbauarbeiten | Wand | Außenwand 7-Schalig | WA-KL |  |  | 0 |  | NEW |  |  | 0 | AllplanAttributes - Ortscode_Geschoßbezeichnung: E00; Sicherheitsklasse: -
 | H2 Ebene 0 | WA-TL | 1105Wa 0811564774 | yes |  | m² | Zimmer- und Holzbauarbeiten | Wand | Außenwand 7-Schalig | WA-TL |  |  | 0 |  | NEW |  |  | 0 | AllplanAttributes - Ortscode_Geschoßbezeichnung: E00; Sicherheitsklasse: -
 | H2 Ebene 0 | WA-HS | 1105Wa 0811564773 | yes |  | m² | Zimmer- und Holzbauarbeiten | Wand | Außenwand 7-Schalig | WA-HS |  |  | 0 |  | NEW |  |  | 0 | AllplanAttributes - Ortscode_Geschoßbezeichnung: E00; Sicherheitsklasse: -
 | H2 Ebene 0 | WA-STB | 1105Wa 0000534161 |  |  | m² | Zimmer- und Holzbauarbeiten | Wand | Außenwand 2-Schalig | WA-STB |  |  | 0 |  |  |  |  | 0 | AllplanAttributes - Ortscode_Geschoßbezeichnung: E00; Sicherheitsklasse: -
 | H2 Ebene 0 | WA-DL | 1105Wa 0000534162 |  |  | m³ | Zimmer- und Holzbauarbeiten | Wand | Außenwand 2-Schalig | WA-DL |  |  | 0 |  |  |  |  | 0 | AllplanAttributes - Ortscode_Geschoßbezeichnung: E00; Sicherheitsklasse: -
 | H2 Ebene 0 | WA-LB | 1105Wa 0000534163 |  |  | m² | Trockenbauarbeiten | Wand | Außenwand 2-Schalig | WA-LB |  |  | 0 |  |  |  |  | 0 | AllplanAttributes - Ortscode_Geschoßbezeichnung: E00; Sicherheitsklasse: -
 | H2 Ebene 0 | WA-KL | 1105Wa 0000534164 |  |  | m² | Zimmer- und Holzbauarbeiten | Wand | Außenwand 2-Schalig | WA-KL |  |  | 0 |  |  |  |  | 0 | AllplanAttributes - Ortscode_Geschoßbezeichnung: E00; Sicherheitsklasse: -
 | H2 Ebene 0 | WA-TL | 1105Wa 0000534165 |  |  | m² | Zimmer- und Holzbauarbeiten | Wand | Außenwand 2-Schalig | WA-TL |  |  | 0 |  |  |  |  | 0 | AllplanAttributes - Ortscode_Geschoßbezeichnung: E00; Sicherheitsklasse: -
 | H2 Ebene 0 | WA-HS | 1105Wa 0000534166 |  |  | m² | Zimmer- und Holzbauarbeiten | Wand | Außenwand 2-Schalig | WA-HS |  |  | 0 |  |  |  |  | 0 | AllplanAttributes - Ortscode_Geschoßbezeichnung: E00; Sicherheitsklasse: -
 | H2 Ebene 0 | WA-DL | 1105Wa 0811649161 |  |  | m³ | Zimmer- und Holzbauarbeiten | Wand | Außenwand 2-Schalig | WA-DL |  |  | 0 |  |  |  |  | 0 | AllplanAttributes - Ortscode_Geschoßbezeichnung: E00; Sicherheitsklasse: -
 | H2 Ebene 0 | WA-LB | 1105Wa 0811649163 |  |  | m² | Trockenbauarbeiten | Wand | Außenwand 2-Schalig | WA-LB |  |  | 0 |  |  |  |  | 0 | AllplanAttributes - Ortscode_Geschoßbezeichnung: E00; Sicherheitsklasse: -
 | H2 Ebene 0 | WA-KL | 1105Wa 0811649165 |  |  | m² | Zimmer- und Holzbauarbeiten | Wand | Außenwand 2-Schalig | WA-KL |  |  | 0 |  |  |  |  | 0 | AllplanAttributes - Ortscode_Geschoßbezeichnung: E00; Sicherheitsklasse: -
 | H2 Ebene 0 | WA-TL | 1105Wa 0811649167 |  |  | m² | Zimmer- und Holzbauarbeiten | Wand | Außenwand 2-Schalig | WA-TL |  |  | 0 |  |  |  |  | 0 | AllplanAttributes - Ortscode_Geschoßbezeichnung: E00; Sicherheitsklasse: -
 | H2 Ebene 0 | WA-HS | 1105Wa 0811649169 |  |  | m² | Zimmer- und Holzbauarbeiten | Wand | Außenwand 2-Schalig | WA-HS |  |  | 0 |  |  |  |  | 0 | AllplanAttributes - Ortscode_Geschoßbezeichnung: E00; Sicherheitsklasse: -
 | H2 Ebene 0 | WA-STB | 1105Wa 0811649159 |  |  | m² | Zimmer- und Holzbauarbeiten | Wand | Außenwand 2-Schalig | WA-STB |  |  | 0 |  |  |  |  | 0 | AllplanAttributes - Ortscode_Geschoßbezeichnung: E00; Sicherheitsklasse: -
 | H2 Ebene 0 | WA-STB | 1105Wa 0811649157 |  |  | m² | Zimmer- und Holzbauarbeiten | Wand | Außenwand 2-Schalig | WA-STB |  |  | 0 |  |  |  |  | 0 | AllplanAttributes - Ortscode_Geschoßbezeichnung: E00; Sicherheitsklasse: -
 | H2 Ebene 0 | WA-DL | 1105Wa 0811649155 |  |  | m³ | Zimmer- und Holzbauarbeiten | Wand | Außenwand 2-Schalig | WA-DL |  |  | 0 |  |  |  |  | 0 | AllplanAttributes - Ortscode_Geschoßbezeichnung: E00; Sicherheitsklasse: -
 | H2 Ebene 0 | WA-LB | 1105Wa 0811649153 |  |  | m² | Trockenbauarbeiten | Wand | Außenwand 2-Schalig | WA-LB |  |  | 0 |  |  |  |  | 0 | AllplanAttributes - Ortscode_Geschoßbezeichnung: E00; Sicherheitsklasse: -
 | H2 Ebene 0 | WA-KL | 1105Wa 0811649151 |  |  | m² | Zimmer- und Holzbauarbeiten | Wand | Außenwand 2-Schalig | WA-KL |  |  | 0 |  |  |  |  | 0 | AllplanAttributes - Ortscode_Geschoßbezeichnung: E00; Sicherheitsklasse: -
 | H2 Ebene 0 | WA-TL | 1105Wa 0811649149 |  |  | m² | Zimmer- und Holzbauarbeiten | Wand | Außenwand 2-Schalig | WA-TL |  |  | 0 |  |  |  |  | 0 | AllplanAttributes - Ortscode_Geschoßbezeichnung: E00; Sicherheitsklasse: -
 | H2 Ebene 0 | WA-HS | 1105Wa 0811649147 |  |  | m² | Zimmer- und Holzbauarbeiten | Wand | Außenwand 2-Schalig | WA-HS |  |  | 0 |  |  |  |  | 0 | AllplanAttributes - Ortscode_Geschoßbezeichnung: E00; Sicherheitsklasse: -
 | H2 Ebene 0 | WA-STB | 1105Wa 0000535976 |  |  | m² | Betonarbeiten | Wand | Außenwand 2-Schalig | WA-STB |  |  | 0 |  |  |  |  | 0 | AllplanAttributes - Ortscode_Geschoßbezeichnung: E00; Sicherheitsklasse: -
 | H2 Ebene 0 | WA-DL | 1105Wa 0000535975 |  |  | m³ | Zimmer- und Holzbauarbeiten | Wand | Außenwand 2-Schalig | WA-DL |  |  | 0 |  |  |  |  | 0 | AllplanAttributes - Ortscode_Geschoßbezeichnung: E00; Sicherheitsklasse: -
 | H2 Ebene 0 | WA-LB | 1105Wa 0000535974 |  |  | m² | Trockenbauarbeiten | Wand | Außenwand 2-Schalig | WA-LB |  |  | 0 |  |  |  |  | 0 | AllplanAttributes - Ortscode_Geschoßbezeichnung: E00; Sicherheitsklasse: -
 | H2 Ebene 0 | WA-KL | 1105Wa 0000535973 |  |  | m² | Zimmer- und Holzbauarbeiten | Wand | Außenwand 2-Schalig | WA-KL |  |  | 0 |  |  |  |  | 0 | AllplanAttributes - Ortscode_Geschoßbezeichnung: E00; Sicherheitsklasse: -
 | H2 Ebene 0 | WA-TL | 1105Wa 0000535972 |  |  | m² | Zimmer- und Holzbauarbeiten | Wand | Außenwand 2-Schalig | WA-TL |  |  | 0 |  |  |  |  | 0 | AllplanAttributes - Ortscode_Geschoßbezeichnung: E00; Sicherheitsklasse: -
 | H2 Ebene 0 | WA-HS | 1105Wa 0000535971 |  |  | m² | Zimmer- und Holzbauarbeiten | Wand | Außenwand 2-Schalig | WA-HS |  |  | 0 |  |  |  |  | 0 | AllplanAttributes - Ortscode_Geschoßbezeichnung: E00; Sicherheitsklasse: -
 | H2 Ebene 0 | WA-STB | 1105Wa 0000002371 | yes |  | m² | Zimmer- und Holzbauarbeiten | Wand | Außenwand 2-Schalig | WA-STB |  |  | 0 |  | NEW |  |  | 0 | AllplanAttributes - Ortscode_Geschoßbezeichnung: E00; Sicherheitsklasse: -
 | H2 Ebene 0 | WA-DL | 1105Wa 0000002367 | yes |  | m³ | Zimmer- und Holzbauarbeiten | Wand | Außenwand 2-Schalig | WA-DL |  |  | 0 |  | NEW |  |  | 0 | AllplanAttributes - Ortscode_Geschoßbezeichnung: E00; Sicherheitsklasse: -
 | H2 Ebene 0 | WA-LB | 1105Wa 0000002365 | yes |  | m² | Trockenbauarbeiten | Wand | Außenwand 2-Schalig | WA-LB |  |  | 0 |  | NEW |  |  | 0 | AllplanAttributes - Ortscode_Geschoßbezeichnung: E00; Sicherheitsklasse: -
 | H2 Ebene 0 | WA-KL | 1105Wa 0000002363 | yes |  | m² | Zimmer- und Holzbauarbeiten | Wand | Außenwand 2-Schalig | WA-KL |  |  | 0 |  | NEW |  |  | 0 | AllplanAttributes - Ortscode_Geschoßbezeichnung: E00; Sicherheitsklasse: -
 | H2 Ebene 0 | WA-TL | 1105Wa 0000002361 | yes |  | m² | Zimmer- und Holzbauarbeiten | Wand | Außenwand 2-Schalig | WA-TL |  |  | 0 |  | NEW |  |  | 0 | AllplanAttributes - Ortscode_Geschoßbezeichnung: E00; Sicherheitsklasse: -
 | H2 Ebene 0 | WA-HS | 1105Wa 0000158330 | yes |  | m² | Zimmer- und Holzbauarbeiten | Wand | Außenwand 2-Schalig | WA-HS |  |  | 0 |  | NEW |  |  | 0 | AllplanAttributes - Ortscode_Geschoßbezeichnung: E00; Sicherheitsklasse: -
 | H2 Ebene 0 | WA-STB | 1105Wa 0000034791 | yes |  | m² | Zimmer- und Holzbauarbeiten | Wand | Außenwand 2-Schalig | WA-STB |  |  | 0 |  | NEW |  |  | 0 | AllplanAttributes - Ortscode_Geschoßbezeichnung: E00; Sicherheitsklasse: -
 | H2 Ebene 0 | WA-DL | 1105Wa 0000034790 | yes |  | m³ | Zimmer- und Holzbauarbeiten | Wand | Außenwand 2-Schalig | WA-DL |  |  | 0 |  | NEW |  |  | 0 | AllplanAttributes - Ortscode_Geschoßbezeichnung: E00; Sicherheitsklasse: -
 | H2 Ebene 0 | WA-LB | 1105Wa 0000034789 | yes |  | m² | Trockenbauarbeiten | Wand | Außenwand 2-Schalig | WA-LB |  |  | 0 |  | NEW |  |  | 0 | AllplanAttributes - Ortscode_Geschoßbezeichnung: E00; Sicherheitsklasse: -
 | H2 Ebene 0 | WA-KL | 1105Wa 0000034788 | yes |  | m² | Zimmer- und Holzbauarbeiten | Wand | Außenwand 2-Schalig | WA-KL |  |  | 0 |  | NEW |  |  | 0 | AllplanAttributes - Ortscode_Geschoßbezeichnung: E00; Sicherheitsklasse: -
 | H2 Ebene 0 | WA-TL | 1105Wa 0000034787 | yes |  | m² | Zimmer- und Holzbauarbeiten | Wand | Außenwand 2-Schalig | WA-TL |  |  | 0 |  | NEW |  |  | 0 | AllplanAttributes - Ortscode_Geschoßbezeichnung: E00; Sicherheitsklasse: -
 | H2 Ebene 0 | WA-HS | 1105Wa 0000158461 | yes |  | m² | Zimmer- und Holzbauarbeiten | Wand | Außenwand 2-Schalig | WA-HS |  |  | 0 |  | NEW |  |  | 0 | AllplanAttributes - Ortscode_Geschoßbezeichnung: E00; Sicherheitsklasse: -
 | H2 Ebene 0 | WA-STB | 1105Wa 0000002369 | yes |  | m² | Zimmer- und Holzbauarbeiten | Wand | Außenwand 2-Schalig | WA-STB |  |  | 0 |  | NEW |  |  | 0 | AllplanAttributes - Ortscode_Geschoßbezeichnung: E00; Sicherheitsklasse: -
 | H2 Ebene 0 | WA-DL | 1105Wa 0000002399 | yes |  | m³ | Zimmer- und Holzbauarbeiten | Wand | Außenwand 2-Schalig | WA-DL |  |  | 0 |  | NEW |  |  | 0 | AllplanAttributes - Ortscode_Geschoßbezeichnung: E00; Sicherheitsklasse: -
 | H2 Ebene 0 | WA-LB | 1105Wa 0000002401 | yes |  | m² | Trockenbauarbeiten | Wand | Außenwand 2-Schalig | WA-LB |  |  | 0 |  | NEW |  |  | 0 | AllplanAttributes - Ortscode_Geschoßbezeichnung: E00; Sicherheitsklasse: -
 | H2 Ebene 0 | WA-KL | 1105Wa 0000002403 | yes |  | m² | Zimmer- und Holzbauarbeiten | Wand | Außenwand 2-Schalig | WA-KL |  |  | 0 |  | NEW |  |  | 0 | AllplanAttributes - Ortscode_Geschoßbezeichnung: E00; Sicherheitsklasse: -
 | H2 Ebene 0 | WA-TL | 1105Wa 0000002405 | yes |  | m² | Zimmer- und Holzbauarbeiten | Wand | Außenwand 2-Schalig | WA-TL |  |  | 0 |  | NEW |  |  | 0 | AllplanAttributes - Ortscode_Geschoßbezeichnung: E00; Sicherheitsklasse: -
 | H2 Ebene 0 | WA-HS | 1105Wa 0000158938 | yes |  | m² | Zimmer- und Holzbauarbeiten | Wand | Außenwand 2-Schalig | WA-HS |  |  | 0 |  | NEW |  |  | 0 | AllplanAttributes - Ortscode_Geschoßbezeichnung: E00; Sicherheitsklasse: -
 | H2 Ebene 0 | WA-STB | 1105Wa 0811406060 | yes |  | m² | Zimmer- und Holzbauarbeiten | Wand | Außenwand 2-Schalig | WA-STB |  |  | 0 |  | NEW |  |  | 0 | AllplanAttributes - Ortscode_Geschoßbezeichnung: E00; Sicherheitsklasse: -
 | H2 Ebene 0 | WA-DL | 1105Wa 0811406061 | yes |  | m³ | Zimmer- und Holzbauarbeiten | Wand | Außenwand 2-Schalig | WA-DL |  |  | 0 |  | NEW |  |  | 0 | AllplanAttributes - Ortscode_Geschoßbezeichnung: E00; Sicherheitsklasse: -
 | H2 Ebene 0 | WA-LB | 1105Wa 0811406062 | yes |  | m² | Trockenbauarbeiten | Wand | Außenwand 2-Schalig | WA-LB |  |  | 0 |  | NEW |  |  | 0 | AllplanAttributes - Ortscode_Geschoßbezeichnung: E00; Sicherheitsklasse: -
 | H2 Ebene 0 | WA-KL | 1105Wa 0811406063 | yes |  | m² | Zimmer- und Holzbauarbeiten | Wand | Außenwand 2-Schalig | WA-KL |  |  | 0 |  | NEW |  |  | 0 | AllplanAttributes - Ortscode_Geschoßbezeichnung: E00; Sicherheitsklasse: -
 | H2 Ebene 0 | WA-TL | 1105Wa 0811406064 | yes |  | m² | Zimmer- und Holzbauarbeiten | Wand | Außenwand 2-Schalig | WA-TL |  |  | 0 |  | NEW |  |  | 0 | AllplanAttributes - Ortscode_Geschoßbezeichnung: E00; Sicherheitsklasse: -
 | H2 Ebene 0 | WA-HS | 1105Wa 0811406065 | yes |  | m² | Zimmer- und Holzbauarbeiten | Wand | Außenwand 2-Schalig | WA-HS |  |  | 0 |  | NEW |  |  | 0 | AllplanAttributes - Ortscode_Geschoßbezeichnung: E00; Sicherheitsklasse: -
 | H2 Ebene 0 | WA-STB | 1105Wa 0811406023 | yes |  | m² | Zimmer- und Holzbauarbeiten | Wand | Außenwand 2-Schalig | WA-STB |  |  | 0 |  | NEW |  |  | 0 | AllplanAttributes - Ortscode_Geschoßbezeichnung: E00; Sicherheitsklasse: -
 | H2 Ebene 0 | WA-DL | 1105Wa 0811406024 | yes |  | m³ | Zimmer- und Holzbauarbeiten | Wand | Außenwand 2-Schalig | WA-DL |  |  | 0 |  | NEW |  |  | 0 | AllplanAttributes - Ortscode_Geschoßbezeichnung: E00; Sicherheitsklasse: -
 | H2 Ebene 0 | WA-LB | 1105Wa 0811406028 | yes |  | m² | Trockenbauarbeiten | Wand | Außenwand 2-Schalig | WA-LB |  |  | 0 |  | NEW |  |  | 0 | AllplanAttributes - Ortscode_Geschoßbezeichnung: E00; Sicherheitsklasse: -
 | H2 Ebene 0 | WA-KL | 1105Wa 0811406025 | yes |  | m² | Zimmer- und Holzbauarbeiten | Wand | Außenwand 2-Schalig | WA-KL |  |  | 0 |  | NEW |  |  | 0 | AllplanAttributes - Ortscode_Geschoßbezeichnung: E00; Sicherheitsklasse: -
 | H2 Ebene 0 | WA-TL | 1105Wa 0811406026 | yes |  | m² | Zimmer- und Holzbauarbeiten | Wand | Außenwand 2-Schalig | WA-TL |  |  | 0 |  | NEW |  |  | 0 | AllplanAttributes - Ortscode_Geschoßbezeichnung: E00; Sicherheitsklasse: -
 | H2 Ebene 0 | WA-HS | 1105Wa 0811406027 | yes |  | m² | Zimmer- und Holzbauarbeiten | Wand | Außenwand 2-Schalig | WA-HS |  |  | 0 |  | NEW |  |  | 0 | AllplanAttributes - Ortscode_Geschoßbezeichnung: E00; Sicherheitsklasse: -
 | H2 Ebene 0 | WA-STB | 1105Wa 0000002989 | yes |  | m² | Zimmer- und Holzbauarbeiten | Wand | Außenwand 2-Schalig | WA-STB |  |  | 0 |  | NEW |  |  | 0 | AllplanAttributes - Ortscode_Geschoßbezeichnung: E00; Sicherheitsklasse: -
 | H2 Ebene 0 | WA-DL | 1105Wa 0000002987 | yes |  | m³ | Zimmer- und Holzbauarbeiten | Wand | Außenwand 2-Schalig | WA-DL |  |  | 0 |  | NEW |  |  | 0 | AllplanAttributes - Ortscode_Geschoßbezeichnung: E00; Sicherheitsklasse: -
 | H2 Ebene 0 | WA-LB | 1105Wa 0000002985 | yes |  | m² | Trockenbauarbeiten | Wand | Außenwand 2-Schalig | WA-LB |  |  | 0 |  | NEW |  |  | 0 | AllplanAttributes - Ortscode_Geschoßbezeichnung: E00; Sicherheitsklasse: -
 | H2 Ebene 0 | WA-KL | 1105Wa 0000002983 | yes |  | m² | Zimmer- und Holzbauarbeiten | Wand | Außenwand 2-Schalig | WA-KL |  |  | 0 |  | NEW |  |  | 0 | AllplanAttributes - Ortscode_Geschoßbezeichnung: E00; Sicherheitsklasse: -
 | H2 Ebene 0 | WA-TL | 1105Wa 0000002981 | yes |  | m² | Zimmer- und Holzbauarbeiten | Wand | Außenwand 2-Schalig | WA-TL |  |  | 0 |  | NEW |  |  | 0 | AllplanAttributes - Ortscode_Geschoßbezeichnung: E00; Sicherheitsklasse: -
 | H2 Ebene 0 | WA-HS | 1105Wa 0000159695 | yes |  | m² | Zimmer- und Holzbauarbeiten | Wand | Außenwand 2-Schalig | WA-HS |  |  | 0 |  | NEW |  |  | 0 | AllplanAttributes - Ortscode_Geschoßbezeichnung: E00; Sicherheitsklasse: -
 | H2 Ebene 0 | WA-STB | 1105Wa 0000003016 | yes |  | m² | Zimmer- und Holzbauarbeiten | Wand | Außenwand 2-Schalig | WA-STB |  |  | 0 |  | NEW |  |  | 0 | AllplanAttributes - Ortscode_Geschoßbezeichnung: E00; Sicherheitsklasse: -
 | H2 Ebene 0 | WA-DL | 1105Wa 0000002967 | yes |  | m³ | Zimmer- und Holzbauarbeiten | Wand | Außenwand 2-Schalig | WA-DL |  |  | 0 |  | NEW |  |  | 0 | AllplanAttributes - Ortscode_Geschoßbezeichnung: E00; Sicherheitsklasse: -
 | H2 Ebene 0 | WA-LB | 1105Wa 0000002971 | yes |  | m² | Trockenbauarbeiten | Wand | Außenwand 2-Schalig | WA-LB |  |  | 0 |  | NEW |  |  | 0 | AllplanAttributes - Ortscode_Geschoßbezeichnung: E00; Sicherheitsklasse: -
 | H2 Ebene 0 | WA-KL | 1105Wa 0000002975 | yes |  | m² | Zimmer- und Holzbauarbeiten | Wand | Außenwand 2-Schalig | WA-KL |  |  | 0 |  | NEW |  |  | 0 | AllplanAttributes - Ortscode_Geschoßbezeichnung: E00; Sicherheitsklasse: -
 | H2 Ebene 0 | WA-TL | 1105Wa 0000002979 | yes |  | m² | Zimmer- und Holzbauarbeiten | Wand | Außenwand 2-Schalig | WA-TL |  |  | 0 |  | NEW |  |  | 0 | AllplanAttributes - Ortscode_Geschoßbezeichnung: E00; Sicherheitsklasse: -
 | H2 Ebene 0 | WA-HS | 1105Wa 0000160617 | yes |  | m² | Zimmer- und Holzbauarbeiten | Wand | Außenwand 2-Schalig | WA-HS |  |  | 0 |  | NEW |  |  | 0 | AllplanAttributes - Ortscode_Geschoßbezeichnung: E00; Sicherheitsklasse: -
 | H2 Ebene 0 | WA-STB | 1105Wa 0000163863 | yes |  | m² | Zimmer- und Holzbauarbeiten | Wand | Außenwand 2-Schalig | WA-STB |  |  | 0 |  | NEW |  |  | 0 | AllplanAttributes - Ortscode_Geschoßbezeichnung: E00; Sicherheitsklasse: -
 | H2 Ebene 0 | WA-DL | 1105Wa 0000163864 | yes |  | m³ | Zimmer- und Holzbauarbeiten | Wand | Außenwand 2-Schalig | WA-DL |  |  | 0 |  | NEW |  |  | 0 | AllplanAttributes - Ortscode_Geschoßbezeichnung: E00; Sicherheitsklasse: -
 | H2 Ebene 0 | WA-LB | 1105Wa 0000163865 | yes |  | m² | Trockenbauarbeiten | Wand | Außenwand 2-Schalig | WA-LB |  |  | 0 |  | NEW |  |  | 0 | AllplanAttributes - Ortscode_Geschoßbezeichnung: E00; Sicherheitsklasse: -
 | H2 Ebene 0 | WA-KL | 1105Wa 0000163866 | yes |  | m² | Zimmer- und Holzbauarbeiten | Wand | Außenwand 2-Schalig | WA-KL |  |  | 0 |  | NEW |  |  | 0 | AllplanAttributes - Ortscode_Geschoßbezeichnung: E00; Sicherheitsklasse: -
 | H2 Ebene 0 | WA-TL | 1105Wa 0000163867 | yes |  | m² | Zimmer- und Holzbauarbeiten | Wand | Außenwand 2-Schalig | WA-TL |  |  | 0 |  | NEW |  |  | 0 | AllplanAttributes - Ortscode_Geschoßbezeichnung: E00; Sicherheitsklasse: -
 | H2 Ebene 0 | WA-HS | 1105Wa 0000163868 | yes |  | m² | Zimmer- und Holzbauarbeiten | Wand | Außenwand 2-Schalig | WA-HS |  |  | 0 |  | NEW |  |  | 0 | AllplanAttributes - Ortscode_Geschoßbezeichnung: E00; Sicherheitsklasse: -
 | H2 Ebene 0 | WA-STB | 1105Wa 0000535390 | yes |  | m² | Betonarbeiten | Wand | Außenwand 2-Schalig | WA-STB |  |  | 0 |  | NEW |  |  | 0 | AllplanAttributes - Ortscode_Geschoßbezeichnung: E00; Sicherheitsklasse: -
 | H2 Ebene 0 | WA-DL | 1105Wa 0000535391 | yes |  | m³ | Zimmer- und Holzbauarbeiten | Wand | Außenwand 2-Schalig | WA-DL |  |  | 0 |  | NEW |  |  | 0 | AllplanAttributes - Ortscode_Geschoßbezeichnung: E00; Sicherheitsklasse: -
 | H2 Ebene 0 | WA-LB | 1105Wa 0000535392 | yes |  | m² | Trockenbauarbeiten | Wand | Außenwand 2-Schalig | WA-LB |  |  | 0 |  | NEW |  |  | 0 | AllplanAttributes - Ortscode_Geschoßbezeichnung: E00; Sicherheitsklasse: -
 | H2 Ebene 0 | WA-KL | 1105Wa 0000535393 | yes |  | m² | Zimmer- und Holzbauarbeiten | Wand | Außenwand 2-Schalig | WA-KL |  |  | 0 |  | NEW |  |  | 0 | AllplanAttributes - Ortscode_Geschoßbezeichnung: E00; Sicherheitsklasse: -
 | H2 Ebene 0 | WA-TL | 1105Wa 0000535394 | yes |  | m² | Zimmer- und Holzbauarbeiten | Wand | Außenwand 2-Schalig | WA-TL |  |  | 0 |  | NEW |  |  | 0 | AllplanAttributes - Ortscode_Geschoßbezeichnung: E00; Sicherheitsklasse: -
 | H2 Ebene 0 | WA-HS | 1105Wa 0000535395 | yes |  | m² | Zimmer- und Holzbauarbeiten | Wand | Außenwand 2-Schalig | WA-HS |  |  | 0 |  | NEW |  |  | 0 | AllplanAttributes - Ortscode_Geschoßbezeichnung: E00; Sicherheitsklasse: -
 | H2 Ebene 0 | WA-STB | 1105Wa 0000019876 | yes |  | m² | Zimmer- und Holzbauarbeiten | Wand | Außenwand 2-Schalig | WA-STB |  |  | 0 |  |  |  |  | 0 | AllplanAttributes - Ortscode_Geschoßbezeichnung: E00; ash D_Detailverweis: X7; ash D_Plannummer: D1861; Sicherheitsklasse: -
 | H2 Ebene 0 | WI-LB | 1105Wa 0000535332 | yes |  | m² | Trockenbauarbeiten | Wand | Außenwand 2-Schalig | WI-LB |  |  | 0 |  | NEW |  |  | 0 |  |  | 42 | AllplanAttributes - Ortscode_Geschoßbezeichnung: E00; ash_W_Trockenbau_Qualitäten: 9; Sicherheitsklasse: -
 | H2 Ebene 0 | WA-STB | 1105Wa 0000535333 | yes |  | m² | Zimmer- und Holzbauarbeiten | Wand | Außenwand 2-Schalig | WA-STB |  |  | 0 |  | NEW |  |  | 0 | AllplanAttributes - Ortscode_Geschoßbezeichnung: E00; ash D_Detailverweis: DT G; ash D_Plannummer: D1853; Sicherheitsklasse: -
 | H2 Ebene 0 | WA-DL | 1105Wa 0000535334 | yes |  | m³ | Zimmer- und Holzbauarbeiten | Wand | Außenwand 2-Schalig | WA-DL |  |  | 0 |  | NEW |  |  | 0 | AllplanAttributes - Ortscode_Geschoßbezeichnung: E00; Sicherheitsklasse: -
 | H2 Ebene 0 | WA-LB | 1105Wa 0000535335 | yes |  | m² | Trockenbauarbeiten | Wand | Außenwand 2-Schalig | WA-LB |  |  | 0 |  | NEW |  |  | 0 | AllplanAttributes - Ortscode_Geschoßbezeichnung: E00; Sicherheitsklasse: -
 | H2 Ebene 0 | WA-KL | 1105Wa 0000535336 | yes |  | m² | Zimmer- und Holzbauarbeiten | Wand | Außenwand 2-Schalig | WA-KL |  |  | 0 |  | NEW |  |  | 0 | AllplanAttributes - Ortscode_Geschoßbezeichnung: E00; Sicherheitsklasse: -
 | H2 Ebene 0 | WA-TL | 1105Wa 0000535337 | yes |  | m² | Zimmer- und Holzbauarbeiten | Wand | Außenwand 2-Schalig | WA-TL |  |  | 0 |  | NEW |  |  | 0 | AllplanAttributes - Ortscode_Geschoßbezeichnung: E00; Sicherheitsklasse: -
 | H2 Ebene 0 | WA-HS | 1105Wa 2005694598 | yes |  | m² | Zimmer- und Holzbauarbeiten | Wand | Außenwand 2-Schalig | WA-HS |  |  | 0 |  | NEW |  |  | 0 | AllplanAttributes - Ortscode_Geschoßbezeichnung: E00; Sicherheitsklasse: -
 | H2 Ebene 0 | WA-STB | 1105Wa 0000538426 | yes |  | m² | Zimmer- und Holzbauarbeiten | Wand | Außenwand 2-Schalig | WA-STB |  |  | 0 |  | NEW | no |  | 0 | AllplanAttributes - Ortscode_Geschoßbezeichnung: E00; Sicherheitsklasse: -
 | H2 Ebene 0 | WA-DL | 1105Wa 0000538427 | yes |  | m³ | Zimmer- und Holzbauarbeiten | Wand | Außenwand 2-Schalig | WA-DL |  |  | 0 |  | NEW | no |  | 0 | AllplanAttributes - Ortscode_Geschoßbezeichnung: E00; Sicherheitsklasse: -
 | H2 Ebene 0 | WA-LB | 1105Wa 0000538428 | yes |  | m² | Trockenbauarbeiten | Wand | Außenwand 2-Schalig | WA-LB |  |  | 0 |  | NEW | no |  | 0 | AllplanAttributes - Ortscode_Geschoßbezeichnung: E00; Sicherheitsklasse: -
 | H2 Ebene 0 | WA-KL | 1105Wa 0000538429 | yes |  | m² | Zimmer- und Holzbauarbeiten | Wand | Außenwand 2-Schalig | WA-KL |  |  | 0 |  | NEW | no |  | 0 | AllplanAttributes - Ortscode_Geschoßbezeichnung: E00; Sicherheitsklasse: -
 | H2 Ebene 0 | WA-TL | 1105Wa 0000538430 | yes |  | m² | Zimmer- und Holzbauarbeiten | Wand | Außenwand 2-Schalig | WA-TL |  |  | 0 |  | NEW | no |  | 0 | AllplanAttributes - Ortscode_Geschoßbezeichnung: E00; Sicherheitsklasse: -
 | H2 Ebene 0 | WA-HS | 1105Wa 0000538431 | yes |  | m² | Zimmer- und Holzbauarbeiten | Wand | Außenwand 2-Schalig | WA-HS |  |  | 0 |  | NEW | no |  | 0 | AllplanAttributes - Ortscode_Geschoßbezeichnung: E00; Sicherheitsklasse: -
 | H2 Ebene 0 | WI-LB | 1105Wa 0000538036 | yes |  | m² | Trockenbauarbeiten | Wand | Außenwand 2-Schalig | WI-LB |  |  | 0 |  | NEW |  |  | 0 |  |  | 42 | AllplanAttributes - Ortscode_Geschoßbezeichnung: E00; ash_W_Trockenbau_Qualitäten: 9; Sicherheitsklasse: -
 | H2 Ebene 0 | WA-STB | 1105Wa 0000538037 | yes |  | m² | Zimmer- und Holzbauarbeiten | Wand | Außenwand 2-Schalig | WA-STB |  |  | 0 |  | NEW |  |  | 0 | AllplanAttributes - Ortscode_Geschoßbezeichnung: E00; ash D_Detailverweis: DT G; ash D_Plannummer: D1853; Sicherheitsklasse: -
 | H2 Ebene 0 | WA-DL | 1105Wa 0000538038 | yes |  | m³ | Zimmer- und Holzbauarbeiten | Wand | Außenwand 2-Schalig | WA-DL |  |  | 0 |  | NEW |  |  | 0 | AllplanAttributes - Ortscode_Geschoßbezeichnung: E00; Sicherheitsklasse: -
 | H2 Ebene 0 | WA-LB | 1105Wa 0000538039 | yes |  | m² | Trockenbauarbeiten | Wand | Außenwand 2-Schalig | WA-LB |  |  | 0 |  | NEW |  |  | 0 | AllplanAttributes - Ortscode_Geschoßbezeichnung: E00; Sicherheitsklasse: -
 | H2 Ebene 0 | WA-KL | 1105Wa 0000538040 | yes |  | m² | Zimmer- und Holzbauarbeiten | Wand | Außenwand 2-Schalig | WA-KL |  |  | 0 |  | NEW |  |  | 0 | AllplanAttributes - Ortscode_Geschoßbezeichnung: E00; Sicherheitsklasse: -
 | H2 Ebene 0 | WA-TL | 1105Wa 0000538041 | yes |  | m² | Zimmer- und Holzbauarbeiten | Wand | Außenwand 2-Schalig | WA-TL |  |  | 0 |  | NEW |  |  | 0 | AllplanAttributes - Ortscode_Geschoßbezeichnung: E00; Sicherheitsklasse: -
 | H2 Ebene 0 | WA-HS | 1105Wa 2005694784 | yes |  | m² | Zimmer- und Holzbauarbeiten | Wand | Außenwand 2-Schalig | WA-HS |  |  | 0 |  | NEW |  |  | 0 | AllplanAttributes - Ortscode_Geschoßbezeichnung: E00; Sicherheitsklasse: -
 | H2 Ebene 0 | WA-STB | 1105Wa 0000035816 |  |  | m² | Zimmer- und Holzbauarbeiten | Wand | Außenwand 2-Schalig | WA-STB |  |  | 0 |  |  |  |  | 0 | AllplanAttributes - Ortscode_Geschoßbezeichnung: E00; Sicherheitsklasse: -
 | H2 Ebene 0 | WA-DL | 1105Wa 0000035817 |  |  | m³ | Zimmer- und Holzbauarbeiten | Wand | Außenwand 2-Schalig | WA-DL |  |  | 0 |  |  |  |  | 0 | AllplanAttributes - Ortscode_Geschoßbezeichnung: E00; Sicherheitsklasse: -
 | H2 Ebene 0 | WA-LB | 1105Wa 0000035818 |  |  | m² | Trockenbauarbeiten | Wand | Außenwand 2-Schalig | WA-LB |  |  | 0 |  |  |  |  | 0 | AllplanAttributes - Ortscode_Geschoßbezeichnung: E00; Sicherheitsklasse: -
 | H2 Ebene 0 | WA-KL | 1105Wa 0000035819 |  |  | m² | Zimmer- und Holzbauarbeiten | Wand | Außenwand 2-Schalig | WA-KL |  |  | 0 |  |  |  |  | 0 | AllplanAttributes - Ortscode_Geschoßbezeichnung: E00; Sicherheitsklasse: -
 | H2 Ebene 0 | WA-TL | 1105Wa 0000035820 |  |  | m² | Zimmer- und Holzbauarbeiten | Wand | Außenwand 2-Schalig | WA-TL |  |  | 0 |  |  |  |  | 0 | AllplanAttributes - Ortscode_Geschoßbezeichnung: E00; Sicherheitsklasse: -
 | H2 Ebene 0 | WA-HS | 1105Wa 0000159880 |  |  | m² | Zimmer- und Holzbauarbeiten | Wand | Außenwand 2-Schalig | WA-HS |  |  | 0 |  |  |  |  | 0 | AllplanAttributes - Ortscode_Geschoßbezeichnung: E00; Sicherheitsklasse: -
 | H2 Ebene 0 | WA-LB | 1105Wa 0811557143 | yes |  | m² | Trockenbauarbeiten | Wand | Außenwand 7-Schalig | WA-LB |  |  | 0 |  | NEW |  |  | 0 | AllplanAttributes - Ortscode_Geschoßbezeichnung: E00; Sicherheitsklasse: -
 | H2 Ebene 0 | WA-LB | 1105Wa 0811557142 | yes |  | m³ | Trockenbauarbeiten | Wand | Außenwand 7-Schalig | WA-LB |  |  | 0 |  | NEW |  |  | 0 | AllplanAttributes - Ortscode_Geschoßbezeichnung: E00; Sicherheitsklasse: -
 | H2 Ebene 0 | WA-HD | 1105Wa 0811557141 | yes |  | m³ | Zimmer- und Holzbauarbeiten | Wand | Außenwand 7-Schalig | WA-HD |  |  | 0 |  | NEW |  |  | 0 | AllplanAttributes - Ortscode_Geschoßbezeichnung: E00; ash D_Detailverweis: DT F; ash D_Plannummer: D1851; Sicherheitsklasse: -
 | H2 Ebene 0 | WA-LB | 1105Wa 0811557140 | yes |  | m³ | Trockenbauarbeiten | Wand | Außenwand 7-Schalig | WA-LB |  |  | 0 |  | NEW |  |  | 0 | AllplanAttributes - Ortscode_Geschoßbezeichnung: E00; Sicherheitsklasse: -
 | H2 Ebene 0 | WA-TP | 1105Wa 0811557139 | yes |  | m² | Trockenbauarbeiten | Wand | Außenwand 7-Schalig | WA-TP |  |  | 0 |  | NEW |  |  | 0 | AllplanAttributes - Ortscode_Geschoßbezeichnung: E00; Sicherheitsklasse: -
 | H2 Ebene 0 | WA-DL | 1105Wa 0811557138 | yes |  | m³ | Zimmer- und Holzbauarbeiten | Wand | Außenwand 7-Schalig | WA-DL |  |  | 0 |  | NEW |  |  | 0 | AllplanAttributes - Ortscode_Geschoßbezeichnung: E00; Sicherheitsklasse: -
 | H2 Ebene 0 | WA-KL | 1105Wa 0811557137 | yes |  | m² | Zimmer- und Holzbauarbeiten | Wand | Außenwand 7-Schalig | WA-KL |  |  | 0 |  | NEW |  |  | 0 | AllplanAttributes - Ortscode_Geschoßbezeichnung: E00; Sicherheitsklasse: -
 | H2 Ebene 0 | WA-TL | 1105Wa 0811557136 | yes |  | m² | Zimmer- und Holzbauarbeiten | Wand | Außenwand 7-Schalig | WA-TL |  |  | 0 |  | NEW |  |  | 0 | AllplanAttributes - Ortscode_Geschoßbezeichnung: E00; Sicherheitsklasse: -
 | H2 Ebene 0 | WA-HS | 1105Wa 0811557135 | yes |  | m² | Zimmer- und Holzbauarbeiten | Wand | Außenwand 7-Schalig | WA-HS |  |  | 0 |  | NEW |  |  | 0 | AllplanAttributes - Ortscode_Geschoßbezeichnung: E00; Sicherheitsklasse: -
 | H2 Ebene 0 | WA-LB | 1105Wa 0811557188 |  |  | m² | Trockenbauarbeiten | Wand | Außenwand 7-Schalig | WA-LB |  |  | 0 |  |  |  |  | 0 | AllplanAttributes - Ortscode_Geschoßbezeichnung: E00; Sicherheitsklasse: -
 | H2 Ebene 0 | WA-LB | 1106Wa 0000000043 | yes | Codetext | m² | Trockenbauarbeiten | Wand | Außenwand 2-Schalig | WA-LB | 0 | A |  | 1106HWa0000000042 | NEW |  | yes | 0 | 0 | no | 0 | no | Codetext
 | H2 Ebene 0 | WA-STB | 1106Wa 0000000044 | yes | Codetext | m² | Betonarbeiten | Wand | Außenwand 2-Schalig | WA-STB | 0 | A |  | 1106HWa0000000042 | NEW |  | yes | 0 | 0 | no | 0 | no | Codetext
 | H2 Ebene 0 | WA-DE | 1106Wa 0000000045 | yes | Codetext | m³ | Wärmedämm-Verbundsysteme | Wand | Außenwand 2-Schalig | WA-DE | 0 | A |  | 1106HWa0000000042 | NEW |  | yes | 0 | 0 | no | 0 | no | Codetext
 | H2 Ebene 0 | WA-LB | 1106Wa 0000000046 | yes | Codetext | m² | Trockenbauarbeiten | Wand | Außenwand 2-Schalig | WA-LB | 0 | A |  | 1106HWa0000000042 | NEW |  | yes | 0 | 0 | no | 0 | no | Codetext
 | H2 Ebene 0 | WA-LB | 1106Wa 0000000074 | yes | Codetext | m² | Trockenbauarbeiten | Wand | Außenwand 2-Schalig | WA-LB | 0 | A |  | 1106HWa0000000073 | NEW |  | yes | 0 | 0 | no | 0 | no | Codetext
 | H2 Ebene 0 | WA-STB | 1106Wa 0000000075 | yes | Codetext | m² | Betonarbeiten | Wand | Außenwand 2-Schalig | WA-STB | 0 | A |  | 1106HWa0000000073 | NEW |  | yes | 0 | 0 | no | 0 | no | Codetext
 | H2 Ebene 0 | WA-DE | 1106Wa 0000000076 | yes | Codetext | m³ | Wärmedämm-Verbundsysteme | Wand | Außenwand 2-Schalig | WA-DE | 0 | A |  | 1106HWa0000000073 | NEW |  | yes | 0 | 0 | no | 0 | no | Codetext
 | H2 Ebene 0 | WA-LB | 1106Wa 0000000077 | yes | Codetext | m² | Trockenbauarbeiten | Wand | Außenwand 2-Schalig | WA-LB | 0 | A |  | 1106HWa0000000073 | NEW |  | yes | 0 | 0 | no | 0 | no | Codetext
 | H2 Ebene 0 | WA-LB | 1106Wa 0000000314 | yes | Codetext | m² | Trockenbauarbeiten | Wand | Außenwand 2-Schalig | WA-LB | 0 | A |  | 1106HWa0000000313 | NEW |  | yes | 0 | 0 | no | 0 | no | Codetext
 | H2 Ebene 0 | WA-STB | 1106Wa 0000000315 | yes | Codetext | m² | Betonarbeiten | Wand | Außenwand 2-Schalig | WA-STB | 0 | A |  | 1106HWa0000000313 | NEW |  | yes | 0 | 0 | no | 0 | no | Codetext
 | H2 Ebene 0 | WA-DE | 1106Wa 0000000316 | yes | Codetext | m³ | Wärmedämm-Verbundsysteme | Wand | Außenwand 2-Schalig | WA-DE | 0 | A |  | 1106HWa0000000313 | NEW |  | yes | 0 | 0 | no | 0 | no | Codetext
 | H2 Ebene 0 | WA-LB | 1106Wa 0000000317 | yes | Codetext | m² | Trockenbauarbeiten | Wand | Außenwand 2-Schalig | WA-LB | 0 | A |  | 1106HWa0000000313 | NEW |  | yes | 0 | 0 | no | 0 | no | Codetext
 | H2 Ebene 0 | WA-LB | 1106Wa 0000000353 | yes | Codetext | m² | Trockenbauarbeiten | Wand | Außenwand 2-Schalig | WA-LB | 0 | A |  | 1106HWa0000000352 | NEW |  | yes | 0 | 0 | no | 0 | no | Codetext
 | H2 Ebene 0 | WA-STB | 1106Wa 0000000354 | yes | Codetext | m² | Betonarbeiten | Wand | Außenwand 2-Schalig | WA-STB | 0 | A |  | 1106HWa0000000352 | NEW |  | yes | 0 | 0 | no | 0 | no | Codetext
 | H2 Ebene 0 | WA-DE | 1106Wa 0000000355 | yes | Codetext | m³ | Wärmedämm-Verbundsysteme | Wand | Außenwand 2-Schalig | WA-DE | 0 | A |  | 1106HWa0000000352 | NEW |  | yes | 0 | 0 | no | 0 | no | Codetext
 | H2 Ebene 0 | WA-LB | 1106Wa 0000000356 | yes | Codetext | m² | Trockenbauarbeiten | Wand | Außenwand 2-Schalig | WA-LB | 0 | A |  | 1106HWa0000000352 | NEW |  | yes | 0 | 0 | no | 0 | no | Codetext
 | H2 Ebene 0 | WA-LB | 1106Wa 0000000392 | yes | Codetext | m² | Trockenbauarbeiten | Wand | Außenwand 2-Schalig | WA-LB | 0 | A |  | 1106HWa0000000391 | NEW |  | yes | 0 | 0 | no | 0 | no | Codetext
 | H2 Ebene 0 | WA-STB | 1106Wa 0000000393 | yes | Codetext | m² | Betonarbeiten | Wand | Außenwand 2-Schalig | WA-STB | 0 | A |  | 1106HWa0000000391 | NEW |  | yes | 0 | 0 | no | 0 | no | Codetext
 | H2 Ebene 0 | WA-DE | 1106Wa 0000000394 | yes | Codetext | m³ | Wärmedämm-Verbundsysteme | Wand | Außenwand 2-Schalig | WA-DE | 0 | A |  | 1106HWa0000000391 | NEW |  | yes | 0 | 0 | no | 0 | no | Codetext
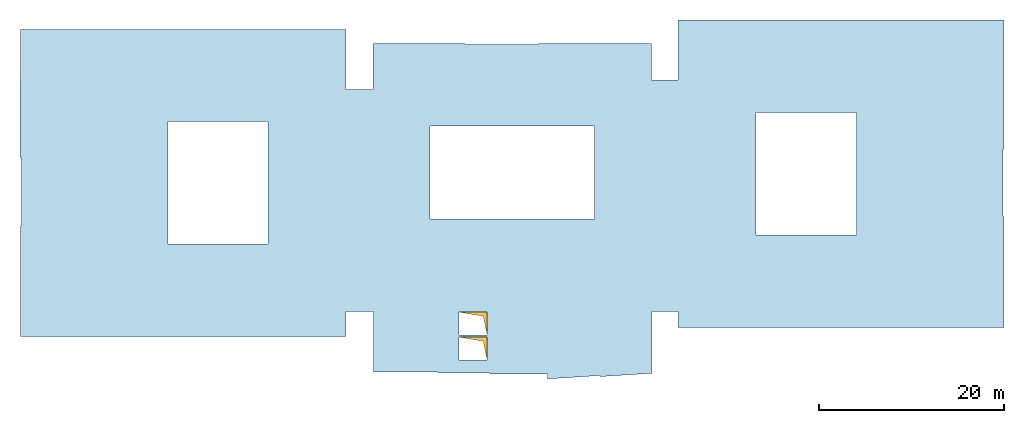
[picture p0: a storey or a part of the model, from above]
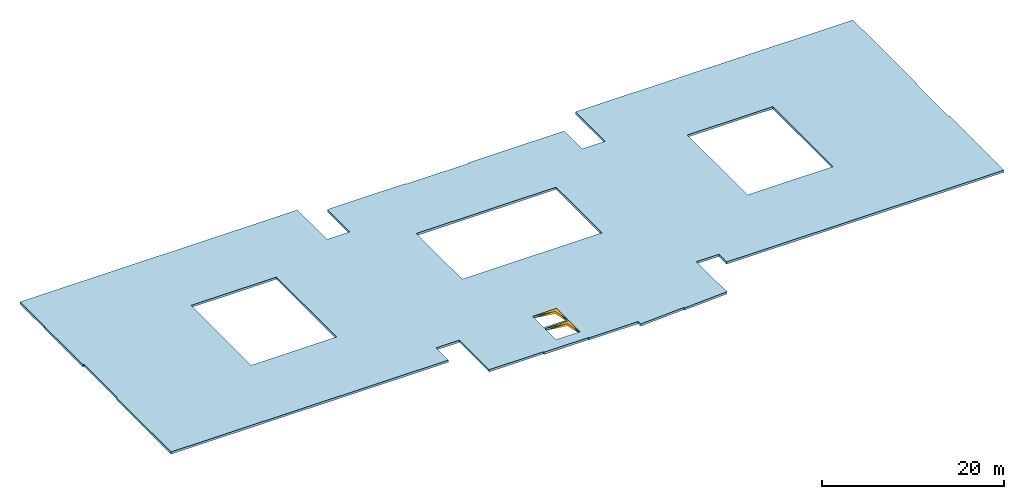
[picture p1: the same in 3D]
Properties of the parts of a building model (IFC4), part 72 of 80

# IfcWall (6826)
Name | In | Material | Allright_Bauteil_ID | 2D Interaktion | Codetext | Abrechnungsart | Gewerk | Objektname | Bezeichnung | AllplanAttributes, Material | Typ = SurfaceSpreadOfFlame | Brandschutzklasse | OKFF | P_ID | Status | LoadBearing | IsExternal | FireRating | ThermalTransmittance (W/K/m2) | Combustible | AcousticRating | Compartmentation | Reference
 | H2 Ebene 0 | WA-LB | 1106Wa 0000000395 | yes | Codetext | m² | Trockenbauarbeiten | Wand | Außenwand 2-Schalig | WA-LB | 0 | A |  | 1106HWa0000000391 | NEW |  | yes | 0 | 0 | no | 0 | no | Codetext
 | H2 Ebene 0 | WA-LB | 1106Wa 0000000431 | yes | Codetext | m² | Trockenbauarbeiten | Wand | Außenwand 2-Schalig | WA-LB | 0 | A |  | 1106HWa0000000430 | NEW |  | yes | 0 | 0 | no | 0 | no | Codetext
 | H2 Ebene 0 | WA-STB | 1106Wa 0000000432 | yes | Codetext | m² | Betonarbeiten | Wand | Außenwand 2-Schalig | WA-STB | 0 | A |  | 1106HWa0000000430 | NEW |  | yes | 0 | 0 | no | 0 | no | Codetext
 | H2 Ebene 0 | WA-DE | 1106Wa 0000000433 | yes | Codetext | m³ | Wärmedämm-Verbundsysteme | Wand | Außenwand 2-Schalig | WA-DE | 0 | A |  | 1106HWa0000000430 | NEW |  | yes | 0 | 0 | no | 0 | no | Codetext
 | H2 Ebene 0 | WA-LB | 1106Wa 0000000434 | yes | Codetext | m² | Trockenbauarbeiten | Wand | Außenwand 2-Schalig | WA-LB | 0 | A |  | 1106HWa0000000430 | NEW |  | yes | 0 | 0 | no | 0 | no | Codetext
 | H2 Ebene 0 | WA-LB | 1106Wa 0000000445 | yes | Codetext | m² | Trockenbauarbeiten | Wand | Außenwand 2-Schalig | WA-LB | 0 | A |  | 1106HWa0000000444 | NEW |  | yes | 0 | 0 | no | 0 | no | Codetext
 | H2 Ebene 0 | WA-STB | 1106Wa 0000000446 | yes | Codetext | m² | Betonarbeiten | Wand | Außenwand 2-Schalig | WA-STB | 0 | A |  | 1106HWa0000000444 | NEW |  | yes | 0 | 0 | no | 0 | no | Codetext
 | H2 Ebene 0 | WA-DE | 1106Wa 0000000447 | yes | Codetext | m³ | Wärmedämm-Verbundsysteme | Wand | Außenwand 2-Schalig | WA-DE | 0 | A |  | 1106HWa0000000444 | NEW |  | yes | 0 | 0 | no | 0 | no | Codetext
 | H2 Ebene 0 | WA-LB | 1106Wa 0000000448 | yes | Codetext | m² | Trockenbauarbeiten | Wand | Außenwand 2-Schalig | WA-LB | 0 | A |  | 1106HWa0000000444 | NEW |  | yes | 0 | 0 | no | 0 | no | Codetext
 | H2 Ebene 0 | WA-LB | 1106Wa 0000000476 | yes | Codetext | m² | Trockenbauarbeiten | Wand | Außenwand 2-Schalig | WA-LB | 0 | A |  | 1106HWa0000000475 | NEW |  | yes | 0 | 0 | no | 0 | no | Codetext
 | H2 Ebene 0 | WA-STB | 1106Wa 0000000477 | yes | Codetext | m² | Betonarbeiten | Wand | Außenwand 2-Schalig | WA-STB | 0 | A |  | 1106HWa0000000475 | NEW |  | yes | 0 | 0 | no | 0 | no | Codetext
 | H2 Ebene 0 | WA-DE | 1106Wa 0000000478 | yes | Codetext | m³ | Wärmedämm-Verbundsysteme | Wand | Außenwand 2-Schalig | WA-DE | 0 | A |  | 1106HWa0000000475 | NEW |  | yes | 0 | 0 | no | 0 | no | Codetext
 | H2 Ebene 0 | WA-LB | 1106Wa 0000000479 | yes | Codetext | m² | Trockenbauarbeiten | Wand | Außenwand 2-Schalig | WA-LB | 0 | A |  | 1106HWa0000000475 | NEW |  | yes | 0 | 0 | no | 0 | no | Codetext
 | H2 Ebene 0 | WA-LB | 1106Wa 0000000593 | yes | Codetext | m² | Trockenbauarbeiten | Wand | Außenwand 2-Schalig | WA-LB | 0 | A |  | 1106HWa0000000592 | NEW |  | yes | 0 | 0 | no | 0 | no | Codetext
 | H2 Ebene 0 | WA-STB | 1106Wa 0000000594 | yes | Codetext | m² | Betonarbeiten | Wand | Außenwand 2-Schalig | WA-STB | 0 | A |  | 1106HWa0000000592 | NEW |  | yes | 0 | 0 | no | 0 | no | Codetext
 | H2 Ebene 0 | WA-DE | 1106Wa 0000000595 | yes | Codetext | m³ | Wärmedämm-Verbundsysteme | Wand | Außenwand 2-Schalig | WA-DE | 0 | A |  | 1106HWa0000000592 | NEW |  | yes | 0 | 0 | no | 0 | no | Codetext
 | H2 Ebene 0 | WA-LB | 1106Wa 0000000596 | yes | Codetext | m² | Trockenbauarbeiten | Wand | Außenwand 2-Schalig | WA-LB | 0 | A |  | 1106HWa0000000592 | NEW |  | yes | 0 | 0 | no | 0 | no | Codetext
 | H2 Ebene 0 | WA-LB | 1106Wa 0000000632 | yes | Codetext | m² | Trockenbauarbeiten | Wand | Außenwand 2-Schalig | WA-LB | 0 | A |  | 1106HWa0000000631 | NEW |  | yes | 0 | 0 | no | 0 | no | Codetext
 | H2 Ebene 0 | WA-STB | 1106Wa 0000000633 | yes | Codetext | m² | Betonarbeiten | Wand | Außenwand 2-Schalig | WA-STB | 0 | A |  | 1106HWa0000000631 | NEW |  | yes | 0 | 0 | no | 0 | no | Codetext
 | H2 Ebene 0 | WA-DE | 1106Wa 0000000634 | yes | Codetext | m³ | Wärmedämm-Verbundsysteme | Wand | Außenwand 2-Schalig | WA-DE | 0 | A |  | 1106HWa0000000631 | NEW |  | yes | 0 | 0 | no | 0 | no | Codetext
 | H2 Ebene 0 | WA-LB | 1106Wa 0000000635 | yes | Codetext | m² | Trockenbauarbeiten | Wand | Außenwand 2-Schalig | WA-LB | 0 | A |  | 1106HWa0000000631 | NEW |  | yes | 0 | 0 | no | 0 | no | Codetext
 | H2 Ebene 0 | WA-LB | 1106Wa 0000001180 | yes | Codetext | m² | Trockenbauarbeiten | Wand | Außenwand 2-Schalig | WA-LB | 0 | A |  | 1106HWa0000001179 | NEW |  | yes | 0 | 0 | no | 0 | no | Codetext
 | H2 Ebene 0 | WA-STB | 1106Wa 0000001181 | yes | Codetext | m² | Betonarbeiten | Wand | Außenwand 2-Schalig | WA-STB | 0 | A |  | 1106HWa0000001179 | NEW |  | yes | 0 | 0 | no | 0 | no | Codetext
 | H2 Ebene 0 | WA-DE | 1106Wa 0000001182 | yes | Codetext | m³ | Wärmedämm-Verbundsysteme | Wand | Außenwand 2-Schalig | WA-DE | 0 | A |  | 1106HWa0000001179 | NEW |  | yes | 0 | 0 | no | 0 | no | Codetext
 | H2 Ebene 0 | WA-LB | 1106Wa 0000001183 | yes | Codetext | m² | Trockenbauarbeiten | Wand | Außenwand 2-Schalig | WA-LB | 0 | A |  | 1106HWa0000001179 | NEW |  | yes | 0 | 0 | no | 0 | no | Codetext
 | H2 Ebene 0 | WA-LB | 1106Wa 0000001239 | yes | Codetext | m² | Trockenbauarbeiten | Wand | Außenwand 2-Schalig | WA-LB | 0 | A |  | 1106HWa0000001238 | NEW |  | yes | 0 | 0 | no | 0 | no | Codetext
 | H2 Ebene 0 | WA-STB | 1106Wa 0000001240 | yes | Codetext | m² | Betonarbeiten | Wand | Außenwand 2-Schalig | WA-STB | 0 | A |  | 1106HWa0000001238 | NEW |  | yes | 0 | 0 | no | 0 | no | Codetext
 | H2 Ebene 0 | WA-DE | 1106Wa 0000001241 | yes | Codetext | m³ | Wärmedämm-Verbundsysteme | Wand | Außenwand 2-Schalig | WA-DE | 0 | A |  | 1106HWa0000001238 | NEW |  | yes | 0 | 0 | no | 0 | no | Codetext
 | H2 Ebene 0 | WA-LB | 1106Wa 0000001242 | yes | Codetext | m² | Trockenbauarbeiten | Wand | Außenwand 2-Schalig | WA-LB | 0 | A |  | 1106HWa0000001238 | NEW |  | yes | 0 | 0 | no | 0 | no | Codetext
 | H2 Ebene 0 | WA-LB | 1106Wa 0000001504 | yes | Codetext | m² | Trockenbauarbeiten | Wand | Außenwand 2-Schalig | WA-LB | 0 | A |  | 1106HWa0000001503 | NEW |  | yes | 0 | 0 | no | 0 | no | Codetext
 | H2 Ebene 0 | WA-STB | 1106Wa 0000001505 | yes | Codetext | m² | Betonarbeiten | Wand | Außenwand 2-Schalig | WA-STB | 0 | A |  | 1106HWa0000001503 | NEW |  | yes | 0 | 0 | no | 0 | no | Codetext
 | H2 Ebene 0 | WA-DE | 1106Wa 0000001506 | yes | Codetext | m³ | Wärmedämm-Verbundsysteme | Wand | Außenwand 2-Schalig | WA-DE | 0 | A |  | 1106HWa0000001503 | NEW |  | yes | 0 | 0 | no | 0 | no | Codetext
 | H2 Ebene 0 | WA-LB | 1106Wa 0000001507 | yes | Codetext | m² | Trockenbauarbeiten | Wand | Außenwand 2-Schalig | WA-LB | 0 | A |  | 1106HWa0000001503 | NEW |  | yes | 0 | 0 | no | 0 | no | Codetext
 | H2 Ebene 0 | WA-LB | 1106Wa 0000001613 | yes | Codetext | m² | Trockenbauarbeiten | Wand | Außenwand 2-Schalig | WA-LB | 0 | A |  | 1106HWa0000001612 | NEW |  | yes | 0 | 0 | no | 0 | no | Codetext
 | H2 Ebene 0 | WA-STB | 1106Wa 0000001614 | yes | Codetext | m² | Betonarbeiten | Wand | Außenwand 2-Schalig | WA-STB | 0 | A |  | 1106HWa0000001612 | NEW |  | yes | 0 | 0 | no | 0 | no | Codetext
 | H2 Ebene 0 | WA-DE | 1106Wa 0000001615 | yes | Codetext | m³ | Wärmedämm-Verbundsysteme | Wand | Außenwand 2-Schalig | WA-DE | 0 | A |  | 1106HWa0000001612 | NEW |  | yes | 0 | 0 | no | 0 | no | Codetext
 | H2 Ebene 0 | WA-LB | 1106Wa 0000001616 | yes | Codetext | m² | Trockenbauarbeiten | Wand | Außenwand 2-Schalig | WA-LB | 0 | A |  | 1106HWa0000001612 | NEW |  | yes | 0 | 0 | no | 0 | no | Codetext
 | H2 Ebene 0 | WA-LB | 1106Wa 0000001697 | yes | Codetext | m² | Trockenbauarbeiten | Wand | Außenwand 2-Schalig | WA-LB | 0 | A |  | 1106HWa0000001696 | NEW |  | yes | 0 | 0 | no | 0 | no | Codetext
 | H2 Ebene 0 | WA-STB | 1106Wa 0000001698 | yes | Codetext | m² | Betonarbeiten | Wand | Außenwand 2-Schalig | WA-STB | 0 | A |  | 1106HWa0000001696 | NEW |  | yes | 0 | 0 | no | 0 | no | Codetext
 | H2 Ebene 0 | WA-DE | 1106Wa 0000001699 | yes | Codetext | m³ | Wärmedämm-Verbundsysteme | Wand | Außenwand 2-Schalig | WA-DE | 0 | A |  | 1106HWa0000001696 | NEW |  | yes | 0 | 0 | no | 0 | no | Codetext
 | H2 Ebene 0 | WA-LB | 1106Wa 0000001700 | yes | Codetext | m² | Trockenbauarbeiten | Wand | Außenwand 2-Schalig | WA-LB | 0 | A |  | 1106HWa0000001696 | NEW |  | yes | 0 | 0 | no | 0 | no | Codetext
 | H2 Ebene 0 | WA-LB | 1106Wa 0000000755 | yes | Codetext | m² | Trockenbauarbeiten | Wand | Außenwand 2-Schalig | WA-LB | 0 | A |  | 1106HWa0000000754 | NEW |  | yes | 0 | 0 | no | 0 | no | Codetext
 | H2 Ebene 0 | WA-STB | 1106Wa 0000000756 | yes | Codetext | m² | Betonarbeiten | Wand | Außenwand 2-Schalig | WA-STB | 0 | A |  | 1106HWa0000000754 | NEW |  | yes | 0 | 0 | no | 0 | no | Codetext
 | H2 Ebene 0 | WA-DE | 1106Wa 0000000757 | yes | Codetext | m³ | Wärmedämm-Verbundsysteme | Wand | Außenwand 2-Schalig | WA-DE | 0 | A |  | 1106HWa0000000754 | NEW |  | yes | 0 | 0 | no | 0 | no | Codetext
 | H2 Ebene 0 | WA-LB | 1106Wa 0000000758 | yes | Codetext | m² | Trockenbauarbeiten | Wand | Außenwand 2-Schalig | WA-LB | 0 | A |  | 1106HWa0000000754 | NEW |  | yes | 0 | 0 | no | 0 | no | Codetext
 | H2 Ebene 0 | WA-LB | 1106Wa 0000000275 | yes | Codetext | m² | Trockenbauarbeiten | Wand | Außenwand 2-Schalig | WA-LB | 0 | A |  | 1106HWa0000000274 | NEW |  | yes | 0 | 0 | no | 0 | no | Codetext
 | H2 Ebene 0 | WA-STB | 1106Wa 0000000276 | yes | Codetext | m² | Betonarbeiten | Wand | Außenwand 2-Schalig | WA-STB | 0 | A |  | 1106HWa0000000274 | NEW |  | yes | 0 | 0 | no | 0 | no | Codetext
 | H2 Ebene 0 | WA-DE | 1106Wa 0000000277 | yes | Codetext | m³ | Wärmedämm-Verbundsysteme | Wand | Außenwand 2-Schalig | WA-DE | 0 | A |  | 1106HWa0000000274 | NEW |  | yes | 0 | 0 | no | 0 | no | Codetext
 | H2 Ebene 0 | WA-LB | 1106Wa 0000000278 | yes | Codetext | m² | Trockenbauarbeiten | Wand | Außenwand 2-Schalig | WA-LB | 0 | A |  | 1106HWa0000000274 | NEW |  | yes | 0 | 0 | no | 0 | no | Codetext
 | H2 Ebene 0 | WA-LB | 1106Wa 0000000888 | yes | Codetext | m² | Trockenbauarbeiten | Wand | Außenwand 2-Schalig | WA-LB | 0 | A |  | 1106HWa0000000886 | NEW |  | yes | 0 | 0 | no | 0 | no | Codetext
 | H2 Ebene 0 | WA-STB | 1106Wa 0000000889 | yes | Codetext | m² | Betonarbeiten | Wand | Außenwand 2-Schalig | WA-STB | 0 | A |  | 1106HWa0000000886 | NEW |  | yes | 0 | 0 | no | 0 | no | Codetext
 | H2 Ebene 0 | WA-DE | 1106Wa 0000000890 | yes | Codetext | m³ | Wärmedämm-Verbundsysteme | Wand | Außenwand 2-Schalig | WA-DE | 0 | A |  | 1106HWa0000000886 | NEW |  | yes | 0 | 0 | no | 0 | no | Codetext
 | H2 Ebene 0 | WA-LB | 1106Wa 0000000891 | yes | Codetext | m² | Trockenbauarbeiten | Wand | Außenwand 2-Schalig | WA-LB | 0 | A |  | 1106HWa0000000886 | NEW |  | yes | 0 | 0 | no | 0 | no | Codetext
 | H2 Ebene 0 | WA-LB | 1106Wa 0000000677 | yes | Codetext | m² | Trockenbauarbeiten | Wand | Außenwand 2-Schalig | WA-LB | 0 | A |  | 1106HWa0000000676 | NEW |  | yes | 0 | 0 | no | 0 | no | Codetext
 | H2 Ebene 0 | WA-STB | 1106Wa 0000000678 | yes | Codetext | m² | Betonarbeiten | Wand | Außenwand 2-Schalig | WA-STB | 0 | A |  | 1106HWa0000000676 | NEW |  | yes | 0 | 0 | no | 0 | no | Codetext
 | H2 Ebene 0 | WA-DE | 1106Wa 0000000679 | yes | Codetext | m³ | Wärmedämm-Verbundsysteme | Wand | Außenwand 2-Schalig | WA-DE | 0 | A |  | 1106HWa0000000676 | NEW |  | yes | 0 | 0 | no | 0 | no | Codetext
 | H2 Ebene 0 | WA-LB | 1106Wa 0000000680 | yes | Codetext | m² | Trockenbauarbeiten | Wand | Außenwand 2-Schalig | WA-LB | 0 | A |  | 1106HWa0000000676 | NEW |  | yes | 0 | 0 | no | 0 | no | Codetext
 | H2 Ebene 0 | WA-LB | 1106Wa 0000000515 | yes | Codetext | m² | Trockenbauarbeiten | Wand | Außenwand 2-Schalig | WA-LB | 0 | A |  | 1106HWa0000000514 | NEW |  | yes | 0 | 0 | no | 0 | no | Codetext
 | H2 Ebene 0 | WA-STB | 1106Wa 0000000516 | yes | Codetext | m² | Betonarbeiten | Wand | Außenwand 2-Schalig | WA-STB | 0 | A |  | 1106HWa0000000514 | NEW |  | yes | 0 | 0 | no | 0 | no | Codetext
 | H2 Ebene 0 | WA-DE | 1106Wa 0000000517 | yes | Codetext | m³ | Wärmedämm-Verbundsysteme | Wand | Außenwand 2-Schalig | WA-DE | 0 | A |  | 1106HWa0000000514 | NEW |  | yes | 0 | 0 | no | 0 | no | Codetext
 | H2 Ebene 0 | WA-LB | 1106Wa 0000000518 | yes | Codetext | m² | Trockenbauarbeiten | Wand | Außenwand 2-Schalig | WA-LB | 0 | A |  | 1106HWa0000000514 | NEW |  | yes | 0 | 0 | no | 0 | no | Codetext
 | H2 Ebene 0 | WA-LB | 1106Wa 0000000716 | yes | Codetext | m² | Trockenbauarbeiten | Wand | Außenwand 2-Schalig | WA-LB | 0 | A |  | 1106HWa0000000715 | NEW |  | yes | 0 | 0 | no | 0 | no | Codetext
 | H2 Ebene 0 | WA-STB | 1106Wa 0000000717 | yes | Codetext | m² | Betonarbeiten | Wand | Außenwand 2-Schalig | WA-STB | 0 | A |  | 1106HWa0000000715 | NEW |  | yes | 0 | 0 | no | 0 | no | Codetext
 | H2 Ebene 0 | WA-DE | 1106Wa 0000000718 | yes | Codetext | m³ | Wärmedämm-Verbundsysteme | Wand | Außenwand 2-Schalig | WA-DE | 0 | A |  | 1106HWa0000000715 | NEW |  | yes | 0 | 0 | no | 0 | no | Codetext
 | H2 Ebene 0 | WA-LB | 1106Wa 0000000719 | yes | Codetext | m² | Trockenbauarbeiten | Wand | Außenwand 2-Schalig | WA-LB | 0 | A |  | 1106HWa0000000715 | NEW |  | yes | 0 | 0 | no | 0 | no | Codetext
 | H2 Ebene 0 | WA-LB | 1106Wa 0000000835 | yes | Codetext | m² | Trockenbauarbeiten | Wand | Außenwand 2-Schalig | WA-LB | 0 | A |  | 1106HWa0000000833 | NEW |  | yes | 0 | 0 | no | 0 | no | Codetext
 | H2 Ebene 0 | WA-STB | 1106Wa 0000000836 | yes | Codetext | m² | Betonarbeiten | Wand | Außenwand 2-Schalig | WA-STB | 0 | A |  | 1106HWa0000000833 | NEW |  | yes | 0 | 0 | no | 0 | no | Codetext
 | H2 Ebene 0 | WA-DE | 1106Wa 0000000837 | yes | Codetext | m³ | Wärmedämm-Verbundsysteme | Wand | Außenwand 2-Schalig | WA-DE | 0 | A |  | 1106HWa0000000833 | NEW |  | yes | 0 | 0 | no | 0 | no | Codetext
 | H2 Ebene 0 | WA-LB | 1106Wa 0000000838 | yes | Codetext | m² | Trockenbauarbeiten | Wand | Außenwand 2-Schalig | WA-LB | 0 | A |  | 1106HWa0000000833 | NEW |  | yes | 0 | 0 | no | 0 | no | Codetext
 | H2 Ebene 0 | WA-LB | 1106Wa 0000000113 | yes | Codetext | m² | Trockenbauarbeiten | Wand | Außenwand 2-Schalig | WA-LB | 0 | A |  | 1106HWa0000000112 | NEW |  | yes | 0 | 0 | no | 0 | no | Codetext
 | H2 Ebene 0 | WA-STB | 1106Wa 0000000114 | yes | Codetext | m² | Betonarbeiten | Wand | Außenwand 2-Schalig | WA-STB | 0 | A |  | 1106HWa0000000112 | NEW |  | yes | 0 | 0 | no | 0 | no | Codetext
 | H2 Ebene 0 | WA-DE | 1106Wa 0000000115 | yes | Codetext | m³ | Wärmedämm-Verbundsysteme | Wand | Außenwand 2-Schalig | WA-DE | 0 | A |  | 1106HWa0000000112 | NEW |  | yes | 0 | 0 | no | 0 | no | Codetext
 | H2 Ebene 0 | WA-LB | 1106Wa 0000000116 | yes | Codetext | m² | Trockenbauarbeiten | Wand | Außenwand 2-Schalig | WA-LB | 0 | A |  | 1106HWa0000000112 | NEW |  | yes | 0 | 0 | no | 0 | no | Codetext
 | H2 Ebene 0 | WA-LB | 1106Wa 0000000230 | yes | Codetext | m² | Trockenbauarbeiten | Wand | Außenwand 2-Schalig | WA-LB | 0 | A |  | 1106HWa0000000229 | NEW |  | yes | 0 | 0 | no | 0 | no | Codetext
 | H2 Ebene 0 | WA-STB | 1106Wa 0000000231 | yes | Codetext | m² | Betonarbeiten | Wand | Außenwand 2-Schalig | WA-STB | 0 | A |  | 1106HWa0000000229 | NEW |  | yes | 0 | 0 | no | 0 | no | Codetext
 | H2 Ebene 0 | WA-DE | 1106Wa 0000000232 | yes | Codetext | m³ | Wärmedämm-Verbundsysteme | Wand | Außenwand 2-Schalig | WA-DE | 0 | A |  | 1106HWa0000000229 | NEW |  | yes | 0 | 0 | no | 0 | no | Codetext
 | H2 Ebene 0 | WA-LB | 1106Wa 0000000233 | yes | Codetext | m² | Trockenbauarbeiten | Wand | Außenwand 2-Schalig | WA-LB | 0 | A |  | 1106HWa0000000229 | NEW |  | yes | 0 | 0 | no | 0 | no | Codetext
 | H2 Ebene 0 | WA-LB | 1106Wa 0000011722 | yes | Codetext | m² | Trockenbauarbeiten | Wand | Außenwand 2-Schalig | WA-LB | 0 | A |  | 1106HWa0000011721 | NEW |  | yes | 0 | 0 | no | 0 | no | Codetext
 | H2 Ebene 0 | WA-STB | 1106Wa 0000011723 | yes | Codetext | m² | Betonarbeiten | Wand | Außenwand 2-Schalig | WA-STB | 0 | A |  | 1106HWa0000011721 | NEW |  | yes | 0 | 0 | no | 0 | no | Codetext
 | H2 Ebene 0 | WA-DE | 1106Wa 0000011724 | yes | Codetext | m³ | Wärmedämm-Verbundsysteme | Wand | Außenwand 2-Schalig | WA-DE | 0 | A |  | 1106HWa0000011721 | NEW |  | yes | 0 | 0 | no | 0 | no | Codetext
 | H2 Ebene 0 | WA-LB | 1106Wa 0000011725 | yes | Codetext | m² | Trockenbauarbeiten | Wand | Außenwand 2-Schalig | WA-LB | 0 | A |  | 1106HWa0000011721 | NEW |  | yes | 0 | 0 | no | 0 | no | Codetext
 | H2 Ebene 0 | WA-LB | 1106Wa 0000000029 | yes | Codetext | m² | Trockenbauarbeiten | Wand | Außenwand 2-Schalig | WA-LB | 0 | A |  | 1106HWa0000000028 | NEW | no | yes | 0 | 0 | no | 0 | no | Codetext
 | H2 Ebene 0 | WA-STB | 1106Wa 0000000030 | yes | Codetext | m² | Betonarbeiten | Wand | Außenwand 2-Schalig | WA-STB | 0 | A |  | 1106HWa0000000028 | NEW | no | yes | 0 | 0 | no | 0 | no | Codetext
 | H2 Ebene 0 | WA-DE | 1106Wa 0000000031 | yes | Codetext | m³ | Wärmedämm-Verbundsysteme | Wand | Außenwand 2-Schalig | WA-DE | 0 | A |  | 1106HWa0000000028 | NEW | no | yes | 0 | 0 | no | 0 | no | Codetext
 | H2 Ebene 0 | WA-LB | 1106Wa 0000000032 | yes | Codetext | m² | Trockenbauarbeiten | Wand | Außenwand 2-Schalig | WA-LB | 0 | A |  | 1106HWa0000000028 | NEW | no | yes | 0 | 0 | no | 0 | no | Codetext
 | H2 Ebene 0 | WA-LB | 1106Wa 0000000794 | yes | Codetext | m² | Trockenbauarbeiten | Wand | Außenwand 2-Schalig | WA-LB | 0 | A |  | 1106HWa0000000793 | NEW |  | yes | 0 | 0 | no | 0 | no | Codetext
 | H2 Ebene 0 | WA-STB | 1106Wa 0000000795 | yes | Codetext | m² | Betonarbeiten | Wand | Außenwand 2-Schalig | WA-STB | 0 | A |  | 1106HWa0000000793 | NEW |  | yes | 0 | 0 | no | 0 | no | Codetext
 | H2 Ebene 0 | WA-DE | 1106Wa 0000000796 | yes | Codetext | m³ | Wärmedämm-Verbundsysteme | Wand | Außenwand 2-Schalig | WA-DE | 0 | A |  | 1106HWa0000000793 | NEW |  | yes | 0 | 0 | no | 0 | no | Codetext
 | H2 Ebene 0 | WA-LB | 1106Wa 0000000797 | yes | Codetext | m² | Trockenbauarbeiten | Wand | Außenwand 2-Schalig | WA-LB | 0 | A |  | 1106HWa0000000793 | NEW |  | yes | 0 | 0 | no | 0 | no | Codetext
 | H2 Ebene 0 | WA-LB | 1106Wa 0000000244 | yes | Codetext | m² | Trockenbauarbeiten | Wand | Außenwand 2-Schalig | WA-LB | 0 | A |  | 1106HWa0000000243 | NEW |  | yes | 0 | 0 | no | 0 | no | Codetext
 | H2 Ebene 0 | WA-STB | 1106Wa 0000000245 | yes | Codetext | m² | Betonarbeiten | Wand | Außenwand 2-Schalig | WA-STB | 0 | A |  | 1106HWa0000000243 | NEW |  | yes | 0 | 0 | no | 0 | no | Codetext
 | H2 Ebene 0 | WA-DE | 1106Wa 0000000246 | yes | Codetext | m³ | Wärmedämm-Verbundsysteme | Wand | Außenwand 2-Schalig | WA-DE | 0 | A |  | 1106HWa0000000243 | NEW |  | yes | 0 | 0 | no | 0 | no | Codetext
 | H2 Ebene 0 | WA-LB | 1106Wa 0000000247 | yes | Codetext | m² | Trockenbauarbeiten | Wand | Außenwand 2-Schalig | WA-LB | 0 | A |  | 1106HWa0000000243 | NEW |  | yes | 0 | 0 | no | 0 | no | Codetext
 | H2 Ebene 0 | WA-LB | 1106Wa 0000013457 | yes | Codetext | m² | Trockenbauarbeiten | Wand | Außenwand 2-Schalig | WA-LB | 0 | A |  | 1106HWa0000001444 | NEW |  | yes | 0 | 0 | no | 0 | no | Codetext
 | H2 Ebene 0 | WA-STB | 1106Wa 0000013456 | yes | Codetext | m² | Betonarbeiten | Wand | Außenwand 2-Schalig | WA-STB | 0 | A |  | 1106HWa0000001444 | NEW |  | yes | 0 | 0 | no | 0 | no | Codetext
 | H2 Ebene 0 | WA-DE | 1106Wa 0000013459 | yes | Codetext | m³ | Wärmedämm-Verbundsysteme | Wand | Außenwand 2-Schalig | WA-DE | 0 | A |  | 1106HWa0000001444 | NEW |  | yes | 0 | 0 | no | 0 | no | Codetext
 | H2 Ebene 0 | WA-LB | 1106Wa 0000013458 | yes | Codetext | m² | Trockenbauarbeiten | Wand | Außenwand 2-Schalig | WA-LB | 0 | A |  | 1106HWa0000001444 | NEW |  | yes | 0 | 0 | no | 0 | no | Codetext
 | H2 Ebene 0 | WA-LB | 1106Wa 0000001445 | yes | Codetext | m² | Trockenbauarbeiten | Wand | Außenwand 2-Schalig | WA-LB | 0 | A |  | 1106HWa0000001444 | NEW |  | yes | 0 | 0 | no | 0 | no | Codetext
 | H2 Ebene 0 | WA-STB | 1106Wa 0000001446 | yes | Codetext | m² | Betonarbeiten | Wand | Außenwand 2-Schalig | WA-STB | 0 | A |  | 1106HWa0000001444 | NEW |  | yes | 0 | 0 | no | 0 | no | Codetext
 | H2 Ebene 0 | WA-DE | 1106Wa 0000001447 | yes | Codetext | m³ | Wärmedämm-Verbundsysteme | Wand | Außenwand 2-Schalig | WA-DE | 0 | A |  | 1106HWa0000001444 | NEW |  | yes | 0 | 0 | no | 0 | no | Codetext
 | H2 Ebene 0 | WA-LB | 1106Wa 0000001448 | yes | Codetext | m² | Trockenbauarbeiten | Wand | Außenwand 2-Schalig | WA-LB | 0 | A |  | 1106HWa0000001444 | NEW |  | yes | 0 | 0 | no | 0 | no | Codetext
 | H2 Ebene 0 | WA-LB | 1106Wa 0000013525 | yes | Codetext | m² | Trockenbauarbeiten | Wand | Außenwand 2-Schalig | WA-LB | 0 | A |  | 1106HWa0000001444 | NEW |  | yes | 0 | 0 | no | 0 | no | Codetext
 | H2 Ebene 0 | WA-STB | 1106Wa 0000013524 | yes | Codetext | m² | Betonarbeiten | Wand | Außenwand 2-Schalig | WA-STB | 0 | A |  | 1106HWa0000001444 | NEW |  | yes | 0 | 0 | no | 0 | no | Codetext
 | H2 Ebene 0 | WA-DE | 1106Wa 0000013523 | yes | Codetext | m³ | Wärmedämm-Verbundsysteme | Wand | Außenwand 2-Schalig | WA-DE | 0 | A |  | 1106HWa0000001444 | NEW |  | yes | 0 | 0 | no | 0 | no | Codetext
 | H2 Ebene 0 | WA-LB | 1106Wa 0000013522 | yes | Codetext | m² | Trockenbauarbeiten | Wand | Außenwand 2-Schalig | WA-LB | 0 | A |  | 1106HWa0000001444 | NEW |  | yes | 0 | 0 | no | 0 | no | Codetext
 | H2 Ebene 0 | WA-LB | 1106Wa 0000000554 | yes | Codetext | m² | Trockenbauarbeiten | Wand | Außenwand 2-Schalig | WA-LB | 0 | A |  | 1106HWa0000000553 | NEW | no | yes | 0 | 0 | no | 0 | no | Codetext
 | H2 Ebene 0 | WA-STB | 1106Wa 0000000555 | yes | Codetext | m² | Betonarbeiten | Wand | Außenwand 2-Schalig | WA-STB | 0 | A |  | 1106HWa0000000553 | NEW | no | yes | 0 | 0 | no | 0 | no | Codetext
 | H2 Ebene 0 | WA-DE | 1106Wa 0000000556 | yes | Codetext | m³ | Wärmedämm-Verbundsysteme | Wand | Außenwand 2-Schalig | WA-DE | 0 | A |  | 1106HWa0000000553 | NEW | no | yes | 0 | 0 | no | 0 | no | Codetext
 | H2 Ebene 0 | WA-LB | 1106Wa 0000000557 | yes | Codetext | m² | Trockenbauarbeiten | Wand | Außenwand 2-Schalig | WA-LB | 0 | A |  | 1106HWa0000000553 | NEW | no | yes | 0 | 0 | no | 0 | no | Codetext
 | H2 Ebene 0 | WA-FAS | 1106Wa 0000014081 | yes | Codetext | m² | Vorgehängte Fassaden | Wand | Außenwand 2-Schalig | WA-FAS | 0 | A |  | 1106HWa0000000475 | NEW |  | yes | 0 | 0 | no | 0 | no | Codetext
 | H2 Ebene 0 | WA-FAS | 1106Wa 0000014648 | yes | Codetext | m² | Vorgehängte Fassaden | Wand | Außenwand 2-Schalig | WA-FAS | 0 | A |  | 1106HWa0000000475 | NEW |  | yes | 0 | 0 | no | 0 | no | Codetext
 | H2 Ebene 0 | WA-STB | 1106Wa 0000014649 | yes | Codetext | m² | Betonarbeiten | Wand | Außenwand 2-Schalig | WA-STB | 0 | A |  | 1106HWa0000000475 | NEW |  | yes | 0 | 0 | no | 0 | no | Codetext
 | H2 Ebene 0 | WA-FAS | 1106Wa 0000014650 | yes | Codetext | m² | Vorgehängte Fassaden | Wand | Außenwand 2-Schalig | WA-FAS | 0 | A |  | 1106HWa0000000475 | NEW |  | yes | 0 | 0 | no | 0 | no | Codetext
 | H2 Ebene 0 | WA-FAS | 1106Wa 0000014651 | yes | Codetext | m² | Vorgehängte Fassaden | Wand | Außenwand 2-Schalig | WA-FAS | 0 | A |  | 1106HWa0000000475 | NEW |  | yes | 0 | 0 | no | 0 | no | Codetext
 | H2 Ebene 0 | WA-FAS | 1106Wa 0000014791 | yes | Codetext | m² | Vorgehängte Fassaden | Wand | Außenwand 2-Schalig | WA-FAS | 0 | A |  | 1106HWa0000000475 | NEW |  | yes | 0 | 0 | no | 0 | no | Codetext
 | H2 Ebene 0 | WA-FAS | 1106Wa 0000014792 | yes | Codetext | m² | Vorgehängte Fassaden | Wand | Außenwand 2-Schalig | WA-FAS | 0 | A |  | 1106HWa0000000475 | NEW |  | yes | 0 | 0 | no | 0 | no | Codetext
 | H2 Ebene 0 | WA-STB | 1106Wa 0000014793 | yes | Codetext | m² | Betonarbeiten | Wand | Außenwand 2-Schalig | WA-STB | 0 | A |  | 1106HWa0000000475 | NEW |  | yes | 0 | 0 | no | 0 | no | Codetext
 | H2 Ebene 0 | WA-FAS | 1106Wa 0000014794 | yes | Codetext | m² | Vorgehängte Fassaden | Wand | Außenwand 2-Schalig | WA-FAS | 0 | A |  | 1106HWa0000000475 | NEW |  | yes | 0 | 0 | no | 0 | no | Codetext
 | H2 Ebene 0 | WA-FAS | 1106Wa 0000014795 | yes | Codetext | m² | Vorgehängte Fassaden | Wand | Außenwand 2-Schalig | WA-FAS | 0 | A |  | 1106HWa0000000475 | NEW |  | yes | 0 | 0 | no | 0 | no | Codetext
 | H2 Ebene 0 | WA-LB | 1106Wa 0000000646 | yes | Codetext | m² | Trockenbauarbeiten | Wand | Außenwand 2-Schalig | WA-LB | 0 | A |  | 1106HWa0000000645 | NEW |  | yes | 0 | 0 | no | 0 | no | Codetext
 | H2 Ebene 0 | WA-STB | 1106Wa 0000000647 | yes | Codetext | m² | Betonarbeiten | Wand | Außenwand 2-Schalig | WA-STB | 0 | A |  | 1106HWa0000000645 | NEW |  | yes | 0 | 0 | no | 0 | no | Codetext
 | H2 Ebene 0 | WA-DE | 1106Wa 0000000648 | yes | Codetext | m³ | Wärmedämm-Verbundsysteme | Wand | Außenwand 2-Schalig | WA-DE | 0 | A |  | 1106HWa0000000645 | NEW |  | yes | 0 | 0 | no | 0 | no | Codetext
 | H2 Ebene 0 | WA-LB | 1106Wa 0000000649 | yes | Codetext | m² | Trockenbauarbeiten | Wand | Außenwand 2-Schalig | WA-LB | 0 | A |  | 1106HWa0000000645 | NEW |  | yes | 0 | 0 | no | 0 | no | Codetext
 | H2 Ebene 0 | WA-LB | 1106Wa 0000001194 | yes | Codetext | m² | Trockenbauarbeiten | Wand | Außenwand 2-Schalig | WA-LB | 0 | A |  | 1106HWa0000001193 | NEW |  | yes | 0 | 0 | no | 0 | no | Codetext
 | H2 Ebene 0 | WA-STB | 1106Wa 0000001195 | yes | Codetext | m² | Betonarbeiten | Wand | Außenwand 2-Schalig | WA-STB | 0 | A |  | 1106HWa0000001193 | NEW |  | yes | 0 | 0 | no | 0 | no | Codetext
 | H2 Ebene 0 | WA-DE | 1106Wa 0000001196 | yes | Codetext | m³ | Wärmedämm-Verbundsysteme | Wand | Außenwand 2-Schalig | WA-DE | 0 | A |  | 1106HWa0000001193 | NEW |  | yes | 0 | 0 | no | 0 | no | Codetext
 | H2 Ebene 0 | WA-LB | 1106Wa 0000001197 | yes | Codetext | m² | Trockenbauarbeiten | Wand | Außenwand 2-Schalig | WA-LB | 0 | A |  | 1106HWa0000001193 | NEW |  | yes | 0 | 0 | no | 0 | no | Codetext
 | H2 Ebene 0 | WA-LB | 1106Wa 0000001225 | yes | Codetext | m² | Trockenbauarbeiten | Wand | Außenwand 2-Schalig | WA-LB | 0 | A |  | 1106HWa0000001224 | NEW |  | yes | 0 | 0 | no | 0 | no | Codetext
 | H2 Ebene 0 | WA-STB | 1106Wa 0000001226 | yes | Codetext | m² | Betonarbeiten | Wand | Außenwand 2-Schalig | WA-STB | 0 | A |  | 1106HWa0000001224 | NEW |  | yes | 0 | 0 | no | 0 | no | Codetext
 | H2 Ebene 0 | WA-DE | 1106Wa 0000001227 | yes | Codetext | m³ | Wärmedämm-Verbundsysteme | Wand | Außenwand 2-Schalig | WA-DE | 0 | A |  | 1106HWa0000001224 | NEW |  | yes | 0 | 0 | no | 0 | no | Codetext
 | H2 Ebene 0 | WA-LB | 1106Wa 0000001228 | yes | Codetext | m² | Trockenbauarbeiten | Wand | Außenwand 2-Schalig | WA-LB | 0 | A |  | 1106HWa0000001224 | NEW |  | yes | 0 | 0 | no | 0 | no | Codetext
 | H2 Ebene 0 | WA-LB | 1106Wa 0000001270 | yes | Codetext | m² | Trockenbauarbeiten | Wand | Außenwand 2-Schalig | WA-LB | 0 | A |  | 1106HWa0000001269 | NEW |  | yes | 0 | 0 | no | 0 | no | Codetext
 | H2 Ebene 0 | WA-STB | 1106Wa 0000001271 | yes | Codetext | m² | Betonarbeiten | Wand | Außenwand 2-Schalig | WA-STB | 0 | A |  | 1106HWa0000001269 | NEW |  | yes | 0 | 0 | no | 0 | no | Codetext
 | H2 Ebene 0 | WA-DE | 1106Wa 0000001272 | yes | Codetext | m³ | Wärmedämm-Verbundsysteme | Wand | Außenwand 2-Schalig | WA-DE | 0 | A |  | 1106HWa0000001269 | NEW |  | yes | 0 | 0 | no | 0 | no | Codetext
 | H2 Ebene 0 | WA-LB | 1106Wa 0000001273 | yes | Codetext | m² | Trockenbauarbeiten | Wand | Außenwand 2-Schalig | WA-LB | 0 | A |  | 1106HWa0000001269 | NEW |  | yes | 0 | 0 | no | 0 | no | Codetext
 | H2 Ebene 0 | WA-LB | 1106Wa 0000001344 | yes | Codetext | m² | Trockenbauarbeiten | Wand | Außenwand 2-Schalig | WA-LB | 0 | A |  | 1106HWa0000001340 | NEW |  | yes | 0 | 0 | no | 0 | no | Codetext
 | H2 Ebene 0 | WA-STB | 1106Wa 0000001343 | yes | Codetext | m² | Betonarbeiten | Wand | Außenwand 2-Schalig | WA-STB | 0 | A |  | 1106HWa0000001340 | NEW |  | yes | 0 | 0 | no | 0 | no | Codetext
 | H2 Ebene 0 | WA-DE | 1106Wa 0000001342 | yes | Codetext | m³ | Wärmedämm-Verbundsysteme | Wand | Außenwand 2-Schalig | WA-DE | 0 | A |  | 1106HWa0000001340 | NEW |  | yes | 0 | 0 | no | 0 | no | Codetext
 | H2 Ebene 0 | WA-LB | 1106Wa 0000001341 | yes | Codetext | m² | Trockenbauarbeiten | Wand | Außenwand 2-Schalig | WA-LB | 0 | A |  | 1106HWa0000001340 | NEW |  | yes | 0 | 0 | no | 0 | no | Codetext
 | H2 Ebene 0 | WA-LB | 1106Wa 0000001490 | yes | Codetext | m² | Trockenbauarbeiten | Wand | Außenwand 2-Schalig | WA-LB | 0 | A |  | 1106HWa0000001489 | NEW |  | yes | 0 | 0 | no | 0 | no | Codetext
 | H2 Ebene 0 | WA-STB | 1106Wa 0000001491 | yes | Codetext | m² | Betonarbeiten | Wand | Außenwand 2-Schalig | WA-STB | 0 | A |  | 1106HWa0000001489 | NEW |  | yes | 0 | 0 | no | 0 | no | Codetext
 | H2 Ebene 0 | WA-DE | 1106Wa 0000001492 | yes | Codetext | m³ | Wärmedämm-Verbundsysteme | Wand | Außenwand 2-Schalig | WA-DE | 0 | A |  | 1106HWa0000001489 | NEW |  | yes | 0 | 0 | no | 0 | no | Codetext
 | H2 Ebene 0 | WA-LB | 1106Wa 0000001493 | yes | Codetext | m² | Trockenbauarbeiten | Wand | Außenwand 2-Schalig | WA-LB | 0 | A |  | 1106HWa0000001489 | NEW |  | yes | 0 | 0 | no | 0 | no | Codetext
 | H2 Ebene 0 | WA-LB | 1106Wa 0000001459 | yes | Codetext | m² | Trockenbauarbeiten | Wand | Außenwand 2-Schalig | WA-LB | 0 | A |  | 1106HWa0000001458 | NEW |  | yes | 0 | 0 | no | 0 | no | Codetext
 | H2 Ebene 0 | WA-STB | 1106Wa 0000001460 | yes | Codetext | m² | Betonarbeiten | Wand | Außenwand 2-Schalig | WA-STB | 0 | A |  | 1106HWa0000001458 | NEW |  | yes | 0 | 0 | no | 0 | no | Codetext
 | H2 Ebene 0 | WA-DE | 1106Wa 0000001461 | yes | Codetext | m³ | Wärmedämm-Verbundsysteme | Wand | Außenwand 2-Schalig | WA-DE | 0 | A |  | 1106HWa0000001458 | NEW |  | yes | 0 | 0 | no | 0 | no | Codetext
 | H2 Ebene 0 | WA-LB | 1106Wa 0000001462 | yes | Codetext | m² | Trockenbauarbeiten | Wand | Außenwand 2-Schalig | WA-LB | 0 | A |  | 1106HWa0000001458 | NEW |  | yes | 0 | 0 | no | 0 | no | Codetext
 | H2 Ebene 0 | WA-LB | 1106Wa 0000012557 | yes | Codetext | m² | Trockenbauarbeiten | Wand | Außenwand 2-Schalig | WA-LB | 0 | A |  | 1106HWa0000012552 | NEW |  | yes | 0 | 0 | no | 0 | no | Codetext
 | H2 Ebene 0 | WA-STB | 1106Wa 0000012556 | yes | Codetext | m² | Betonarbeiten | Wand | Außenwand 2-Schalig | WA-STB | 0 | A |  | 1106HWa0000012552 | NEW |  | yes | 0 | 0 | no | 0 | no | Codetext
 | H2 Ebene 0 | WA-DE | 1106Wa 0000012555 | yes | Codetext | m³ | Wärmedämm-Verbundsysteme | Wand | Außenwand 2-Schalig | WA-DE | 0 | A |  | 1106HWa0000012552 | NEW |  | yes | 0 | 0 | no | 0 | no | Codetext
 | H2 Ebene 0 | WA-LB | 1106Wa 0000012554 | yes | Codetext | m² | Trockenbauarbeiten | Wand | Außenwand 2-Schalig | WA-LB | 0 | A |  | 1106HWa0000012552 | NEW |  | yes | 0 | 0 | no | 0 | no | Codetext
 | H2 Ebene 0 | WA-LB | 1106Wa 0000012502 | yes | Codetext | m² | Trockenbauarbeiten | Wand | Außenwand 2-Schalig | WA-LB | 0 | A |  | 1106HWa0000012500 | NEW |  | yes | 0 | 0 | no | 0 | no | Codetext
 | H2 Ebene 0 | WA-STB | 1106Wa 0000012503 | yes | Codetext | m² | Betonarbeiten | Wand | Außenwand 2-Schalig | WA-STB | 0 | A |  | 1106HWa0000012500 | NEW |  | yes | 0 | 0 | no | 0 | no | Codetext
 | H2 Ebene 0 | WA-DE | 1106Wa 0000012505 | yes | Codetext | m³ | Wärmedämm-Verbundsysteme | Wand | Außenwand 2-Schalig | WA-DE | 0 | A |  | 1106HWa0000012500 | NEW |  | yes | 0 | 0 | no | 0 | no | Codetext
 | H2 Ebene 0 | WA-LB | 1106Wa 0000012501 | yes | Codetext | m² | Trockenbauarbeiten | Wand | Außenwand 2-Schalig | WA-LB | 0 | A |  | 1106HWa0000012500 | NEW |  | yes | 0 | 0 | no | 0 | no | Codetext
 | H2 Ebene 0 | WA-LB | 1106Wa 0000001728 | yes | Codetext | m² | Trockenbauarbeiten | Wand | Außenwand 2-Schalig | WA-LB | 0 | A |  | 1106HWa0000001727 | NEW |  | yes | 0 | 0 | no | 0 | no | Codetext
 | H2 Ebene 0 | WA-STB | 1106Wa 0000001729 | yes | Codetext | m² | Betonarbeiten | Wand | Außenwand 2-Schalig | WA-STB | 0 | A |  | 1106HWa0000001727 | NEW |  | yes | 0 | 0 | no | 0 | no | Codetext
 | H2 Ebene 0 | WA-DE | 1106Wa 0000001730 | yes | Codetext | m³ | Wärmedämm-Verbundsysteme | Wand | Außenwand 2-Schalig | WA-DE | 0 | A |  | 1106HWa0000001727 | NEW |  | yes | 0 | 0 | no | 0 | no | Codetext
 | H2 Ebene 0 | WA-LB | 1106Wa 0000001731 | yes | Codetext | m² | Trockenbauarbeiten | Wand | Außenwand 2-Schalig | WA-LB | 0 | A |  | 1106HWa0000001727 | NEW |  | yes | 0 | 0 | no | 0 | no | Codetext
 | H2 Ebene 0 | WA-LB | 1106Wa 0000001599 | yes | Codetext | m² | Trockenbauarbeiten | Wand | Außenwand 2-Schalig | WA-LB | 0 | A |  | 1106HWa0000001598 | NEW |  | yes | 0 | 0 | no | 0 | no | Codetext
 | H2 Ebene 0 | WA-STB | 1106Wa 0000001600 | yes | Codetext | m² | Betonarbeiten | Wand | Außenwand 2-Schalig | WA-STB | 0 | A |  | 1106HWa0000001598 | NEW |  | yes | 0 | 0 | no | 0 | no | Codetext
 | H2 Ebene 0 | WA-DE | 1106Wa 0000001601 | yes | Codetext | m³ | Wärmedämm-Verbundsysteme | Wand | Außenwand 2-Schalig | WA-DE | 0 | A |  | 1106HWa0000001598 | NEW |  | yes | 0 | 0 | no | 0 | no | Codetext
 | H2 Ebene 0 | WA-LB | 1106Wa 0000001602 | yes | Codetext | m² | Trockenbauarbeiten | Wand | Außenwand 2-Schalig | WA-LB | 0 | A |  | 1106HWa0000001598 | NEW |  | yes | 0 | 0 | no | 0 | no | Codetext
 | H2 Ebene 0 | WA-LB | 1106Wa 0000001683 | yes | Codetext | m² | Trockenbauarbeiten | Wand | Außenwand 2-Schalig | WA-LB | 0 | A |  | 1106HWa0000001682 | NEW |  | yes | 0 | 0 | no | 0 | no | Codetext
 | H2 Ebene 0 | WA-STB | 1106Wa 0000001684 | yes | Codetext | m² | Betonarbeiten | Wand | Außenwand 2-Schalig | WA-STB | 0 | A |  | 1106HWa0000001682 | NEW |  | yes | 0 | 0 | no | 0 | no | Codetext
 | H2 Ebene 0 | WA-DE | 1106Wa 0000001685 | yes | Codetext | m³ | Wärmedämm-Verbundsysteme | Wand | Außenwand 2-Schalig | WA-DE | 0 | A |  | 1106HWa0000001682 | NEW |  | yes | 0 | 0 | no | 0 | no | Codetext
 | H2 Ebene 0 | WA-LB | 1106Wa 0000001686 | yes | Codetext | m² | Trockenbauarbeiten | Wand | Außenwand 2-Schalig | WA-LB | 0 | A |  | 1106HWa0000001682 | NEW |  | yes | 0 | 0 | no | 0 | no | Codetext
 | H2 Ebene 0 | WA-LB | 1106Wa 0000001644 | yes | Codetext | m² | Trockenbauarbeiten | Wand | Außenwand 2-Schalig | WA-LB | 0 | A |  | 1106HWa0000001643 | NEW |  | yes | 0 | 0 | no | 0 | no | Codetext
 | H2 Ebene 0 | WA-STB | 1106Wa 0000001645 | yes | Codetext | m² | Betonarbeiten | Wand | Außenwand 2-Schalig | WA-STB | 0 | A |  | 1106HWa0000001643 | NEW |  | yes | 0 | 0 | no | 0 | no | Codetext
 | H2 Ebene 0 | WA-DE | 1106Wa 0000001646 | yes | Codetext | m³ | Wärmedämm-Verbundsysteme | Wand | Außenwand 2-Schalig | WA-DE | 0 | A |  | 1106HWa0000001643 | NEW |  | yes | 0 | 0 | no | 0 | no | Codetext
 | H2 Ebene 0 | WA-LB | 1106Wa 0000001647 | yes | Codetext | m² | Trockenbauarbeiten | Wand | Außenwand 2-Schalig | WA-LB | 0 | A |  | 1106HWa0000001643 | NEW |  | yes | 0 | 0 | no | 0 | no | Codetext
WV 1.1 | H2 Ebene 0 |  | 1113Sma0814159199 |  | VUK1 - Hängeschrank | St | Trockenbauarbeiten | SmartPart | WV 1.1 |  |  |  | 0.2 |  |  |  |  | - | AllplanAttributes - Text1: WA2020; UK: 0 m; OK: 0 m; V6: 0 m; V7: 0 m; V8: 0 m; V9: 0; Länge: 0.8 m; Dicke: 0.025 m; Höhe: 0.2 m; Programmversion: 3.1; Text3: 0; Plugin_Bezeichnung: MainObject; Plugin_Objektname: SmartPartCompressed; Version: 1.1; Abstand_Öffn_Unten: 2 m; ash T_Feuchtebeständigkeit: nein; Feuerwiderstandsklasse~: nein
WV 1.1 | H2 Ebene 0 |  | 1113Sma0814159213 |  | VUK1 - Desinfektionsmittelspender | St | Trockenbauarbeiten | SmartPart | WV 1.1 |  |  |  | 0.2 |  |  |  |  | - | AllplanAttributes - Text1: WA2020; UK: 0 m; OK: 0 m; V6: 0 m; V7: 0 m; V8: 0 m; V9: 0; Länge: 0.2 m; Dicke: 0.025 m; Höhe: 0.3 m; Programmversion: 3.1; Text3: 0; Plugin_Bezeichnung: MainObject; Plugin_Objektname: SmartPartCompressed; Version: 1.1; Abstand_Öffn_Unten: 1.26 m; ash T_Feuchtebeständigkeit: nein; Feuerwiderstandsklasse~: nein
WV 1.1 | H2 Ebene 0 |  | 1113Sma0814159242 |  | VUK1 - Monitor | St | Trockenbauarbeiten | SmartPart | WV 1.1 |  |  |  | 0.2 |  |  |  |  | - | AllplanAttributes - Text1: WA2030; UK: 0 m; OK: 0 m; V6: 0 m; V7: 0 m; V8: 0 m; V9: 0; Länge: 1.2 m; Dicke: 0.025 m; Höhe: 1 m; Programmversion: 3.1; Text3: 0; Plugin_Bezeichnung: MainObject; Plugin_Objektname: SmartPartCompressed; Version: 1.1; Abstand_Öffn_Unten: 1.1 m; ash T_Feuchtebeständigkeit: nein; Feuerwiderstandsklasse~: nein
WV 1.1 | H2 Ebene 0 |  | 1113Sma0814159255 |  | VUK1 - Monitor | St | Trockenbauarbeiten | SmartPart | WV 1.1 |  |  |  | 0.2 |  |  |  |  | - | AllplanAttributes - Text1: WA2030; UK: 0 m; OK: 0 m; V6: 0 m; V7: 0 m; V8: 0 m; V9: 0; Länge: 1.2 m; Dicke: 0.025 m; Höhe: 1 m; Programmversion: 3.1; Text3: 0; Plugin_Bezeichnung: MainObject; Plugin_Objektname: SmartPartCompressed; Version: 1.1; Abstand_Öffn_Unten: 1.1 m; ash T_Feuchtebeständigkeit: nein; Feuerwiderstandsklasse~: nein
WV 1.1 | H2 Ebene 0 |  | 1113Sma0814159269 |  | VUK1 - Hängeschrank | St | Trockenbauarbeiten | SmartPart | WV 1.1 |  |  |  | 0.2 |  |  |  |  | - | AllplanAttributes - Text1: WA2008; UK: 0 m; OK: 0 m; V6: 0 m; V7: 0 m; V8: 0 m; V9: 0; Länge: 2.2 m; Dicke: 0.025 m; Höhe: 0.2 m; Programmversion: 3.1; Text3: 0; Plugin_Bezeichnung: MainObject; Plugin_Objektname: SmartPartCompressed; Version: 1.1; Abstand_Öffn_Unten: 2.35 m; ash T_Feuchtebeständigkeit: nein; Feuerwiderstandsklasse~: nein
WV 1.1 | H2 Ebene 0 |  | 1113Sma0814159282 |  | VUK1 - Hängeschrank | St | Trockenbauarbeiten | SmartPart | WV 1.1 |  |  |  | 0.2 |  |  |  |  | - | AllplanAttributes - Text1: WA2008; UK: 0 m; OK: 0 m; V6: 0 m; V7: 0 m; V8: 0 m; V9: 0; Länge: 2.2 m; Dicke: 0.025 m; Höhe: 0.2 m; Programmversion: 3.1; Text3: 0; Plugin_Bezeichnung: MainObject; Plugin_Objektname: SmartPartCompressed; Version: 1.1; Abstand_Öffn_Unten: 2.35 m; ash T_Feuchtebeständigkeit: nein; Feuerwiderstandsklasse~: nein
WV 1.1 | H2 Ebene 0 |  | 1113Sma0814159296 |  | VUK1 - Hängeschrank | St | Trockenbauarbeiten | SmartPart | WV 1.1 |  |  |  | 0.2 |  |  |  |  | - | AllplanAttributes - Text1: WA2008; UK: 0 m; OK: 0 m; V6: 0 m; V7: 0 m; V8: 0 m; V9: 0; Länge: 4.65 m; Dicke: 0.025 m; Höhe: 0.2 m; Programmversion: 3.1; Text3: 0; Plugin_Bezeichnung: MainObject; Plugin_Objektname: SmartPartCompressed; Version: 1.1; Abstand_Öffn_Unten: 2.35 m; ash T_Feuchtebeständigkeit: nein; Feuerwiderstandsklasse~: nein
WV 1.1 | H2 Ebene 0 |  | 1113Sma0814159309 |  | VUK1 - Hängeschrank | St | Trockenbauarbeiten | SmartPart | WV 1.1 |  |  |  | 0.2 |  |  |  |  | - | AllplanAttributes - Text1: WA2008; UK: 0 m; OK: 0 m; V6: 0 m; V7: 0 m; V8: 0 m; V9: 0; Länge: 4.65 m; Dicke: 0.025 m; Höhe: 0.2 m; Programmversion: 3.1; Text3: 0; Plugin_Bezeichnung: MainObject; Plugin_Objektname: SmartPartCompressed; Version: 1.1; Abstand_Öffn_Unten: 2.35 m; ash T_Feuchtebeständigkeit: nein; Feuerwiderstandsklasse~: nein
WV 1.1 | H2 Ebene 0 |  | 1113Sma0814159324 |  | VUK1 - Desinfektionsmittelspender | St | Trockenbauarbeiten | SmartPart | WV 1.1 |  |  |  | 0.2 |  |  |  |  | - | AllplanAttributes - Text1: WA2016; UK: 0 m; OK: 0 m; V6: 0 m; V7: 0 m; V8: 0 m; V9: 0; Länge: 0.2 m; Dicke: 0.025 m; Höhe: 0.3 m; Programmversion: 3.1; Text3: 0; Plugin_Bezeichnung: MainObject; Plugin_Objektname: SmartPartCompressed; Version: 1.1; Abstand_Öffn_Unten: 1.26 m; ash T_Feuchtebeständigkeit: nein; Feuerwiderstandsklasse~: nein
WV 1.1 | H2 Ebene 0 |  | 1113Sma0814159337 |  | VUK1 - Desinfektionsmittelspender | St | Trockenbauarbeiten | SmartPart | WV 1.1 |  |  |  | 0.2 |  |  |  |  | - | AllplanAttributes - Text1: WA2016; UK: 0 m; OK: 0 m; V6: 0 m; V7: 0 m; V8: 0 m; V9: 0; Länge: 0.2 m; Dicke: 0.025 m; Höhe: 0.3 m; Programmversion: 3.1; Text3: 0; Plugin_Bezeichnung: MainObject; Plugin_Objektname: SmartPartCompressed; Version: 1.1; Abstand_Öffn_Unten: 1.26 m; ash T_Feuchtebeständigkeit: nein; Feuerwiderstandsklasse~: nein
WV 1.1 | H2 Ebene 0 |  | 1113Sma0814159351 |  | VUK1 - Haltegriff | St | Trockenbauarbeiten | SmartPart | WV 1.1 |  |  |  | 0.2 |  |  |  |  | - | AllplanAttributes - Text1: WA2018; UK: 0 m; OK: 0 m; V6: 0 m; V7: 0 m; V8: 0 m; V9: 0; Länge: 1.6 m; Dicke: 0.025 m; Höhe: 0.2 m; Programmversion: 3.1; Text3: 0; Plugin_Bezeichnung: MainObject; Plugin_Objektname: SmartPartCompressed; Version: 1.1; Abstand_Öffn_Unten: 1.55 m; ash T_Feuchtebeständigkeit: nein; Feuerwiderstandsklasse~: nein
WV 1.1 | H2 Ebene 0 |  | 1113Sma0814159364 |  | VUK1 - Haltegriff | St | Trockenbauarbeiten | SmartPart | WV 1.1 |  |  |  | 0.2 |  |  |  |  | - | AllplanAttributes - Text1: WA2018; UK: 0 m; OK: 0 m; V6: 0 m; V7: 0 m; V8: 0 m; V9: 0; Länge: 1.6 m; Dicke: 0.025 m; Höhe: 0.2 m; Programmversion: 3.1; Text3: 0; Plugin_Bezeichnung: MainObject; Plugin_Objektname: SmartPartCompressed; Version: 1.1; Abstand_Öffn_Unten: 1.55 m; ash T_Feuchtebeständigkeit: nein; Feuerwiderstandsklasse~: nein
WV 1.1 | H2 Ebene 0 |  | 1113Sma0814159405 |  | VUK1 - Hängeschrank | St | Trockenbauarbeiten | SmartPart | WV 1.1 |  |  |  | 0.2 |  |  |  |  | - | AllplanAttributes - Text1: WA2018; UK: 0 m; OK: 0 m; V6: 0 m; V7: 0 m; V8: 0 m; V9: 0; Länge: 1.5 m; Dicke: 0.025 m; Höhe: 0.2 m; Programmversion: 3.1; Text3: 0; Plugin_Bezeichnung: MainObject; Plugin_Objektname: SmartPartCompressed; Version: 1.1; Abstand_Öffn_Unten: 2.35 m; ash T_Feuchtebeständigkeit: nein; Feuerwiderstandsklasse~: nein
WV 1.1 | H2 Ebene 0 |  | 1113Sma0814159432 |  | VUK1 - Hängeschrank | St | Trockenbauarbeiten | SmartPart | WV 1.1 |  |  |  | 0.2 |  |  |  |  | - | AllplanAttributes - Text1: WA2018; UK: 0 m; OK: 0 m; V6: 0 m; V7: 0 m; V8: 0 m; V9: 0; Länge: 3.76 m; Dicke: 0.025 m; Höhe: 0.2 m; Programmversion: 3.1; Text3: 0; Plugin_Bezeichnung: MainObject; Plugin_Objektname: SmartPartCompressed; Version: 1.1; Abstand_Öffn_Unten: 2.35 m; ash T_Feuchtebeständigkeit: nein; Feuerwiderstandsklasse~: nein
WV 1.1 | H2 Ebene 0 |  | 1113Sma0814159446 |  | VUK1 - Desinfektionsmittelspender | St | Trockenbauarbeiten | SmartPart | WV 1.1 |  |  |  | 0.2 |  |  |  |  | - | AllplanAttributes - Text1: WA2018; UK: 0 m; OK: 0 m; V6: 0 m; V7: 0 m; V8: 0 m; V9: 0; Länge: 0.2 m; Dicke: 0.025 m; Höhe: 0.3 m; Programmversion: 3.1; Text3: 0; Plugin_Bezeichnung: MainObject; Plugin_Objektname: SmartPartCompressed; Version: 1.1; Abstand_Öffn_Unten: 1.26 m; ash T_Feuchtebeständigkeit: nein; Feuerwiderstandsklasse~: nein
WV 1.1 | H2 Ebene 0 |  | 1113Sma0814159460 |  | VUK1 - Desinfektionsmittelspender | St | Trockenbauarbeiten | SmartPart | WV 1.1 |  |  |  | 0.2 |  |  |  |  | - | AllplanAttributes - Text1: WA2018; UK: 0 m; OK: 0 m; V6: 0 m; V7: 0 m; V8: 0 m; V9: 0; Länge: 0.2 m; Dicke: 0.025 m; Höhe: 0.3 m; Programmversion: 3.1; Text3: 0; Plugin_Bezeichnung: MainObject; Plugin_Objektname: SmartPartCompressed; Version: 1.1; Abstand_Öffn_Unten: 1.26 m; ash T_Feuchtebeständigkeit: nein; Feuerwiderstandsklasse~: nein
WV 1.1 | H2 Ebene 0 |  | 1113Sma0814159474 |  | VUK1 - Hängeschrank | St | Trockenbauarbeiten | SmartPart | WV 1.1 |  |  |  | 0.2 |  |  |  |  | - | AllplanAttributes - Text1: WA2018; UK: 0 m; OK: 0 m; V6: 0 m; V7: 0 m; V8: 0 m; V9: 0; Länge: 5.74 m; Dicke: 0.025 m; Höhe: 0.2 m; Programmversion: 3.1; Text3: 0; Plugin_Bezeichnung: MainObject; Plugin_Objektname: SmartPartCompressed; Version: 1.1; Abstand_Öffn_Unten: 2.35 m; ash T_Feuchtebeständigkeit: nein; Feuerwiderstandsklasse~: nein
WV 1.1 | H2 Ebene 0 |  | 1113Sma0814159516 |  | VUK1 - Desinfektionsmittelspender | St | Trockenbauarbeiten | SmartPart | WV 1.1 |  |  |  | 0.2 |  |  |  |  | - | AllplanAttributes - Text1: WA2020; UK: 0 m; OK: 0 m; V6: 0 m; V7: 0 m; V8: 0 m; V9: 0; Länge: 0.2 m; Dicke: 0.025 m; Höhe: 0.3 m; Programmversion: 3.1; Text3: 0; Plugin_Bezeichnung: MainObject; Plugin_Objektname: SmartPartCompressed; Version: 1.1; Abstand_Öffn_Unten: 1.26 m; ash T_Feuchtebeständigkeit: nein; Feuerwiderstandsklasse~: nein
WV 1.1 | H2 Ebene 0 |  | 1113Sma0814159530 |  | VUK1 - Hängeschrank | St | Trockenbauarbeiten | SmartPart | WV 1.1 |  |  |  | 0.2 |  |  |  |  | - | AllplanAttributes - Text1: WA2020; UK: 0 m; OK: 0 m; V6: 0 m; V7: 0 m; V8: 0 m; V9: 0; Länge: 0.8 m; Dicke: 0.025 m; Höhe: 0.2 m; Programmversion: 3.1; Text3: 0; Plugin_Bezeichnung: MainObject; Plugin_Objektname: SmartPartCompressed; Version: 1.1; Abstand_Öffn_Unten: 2.2 m; ash T_Feuchtebeständigkeit: nein; Feuerwiderstandsklasse~: nein
WV 1.1 | H2 Ebene 0 |  | 1113Sma0814159544 |  | VUK1 - Lichtleiste (ELT) | St | Trockenbauarbeiten | SmartPart | WV 1.1 |  |  |  | 0.2 |  |  |  |  | - | AllplanAttributes - Text1: WA2004; UK: 0 m; OK: 0 m; V6: 0 m; V7: 0 m; V8: 0 m; V9: 0; Länge: 1.2 m; Dicke: 0.025 m; Höhe: 0.15 m; Programmversion: 3.1; Text3: 0; Plugin_Bezeichnung: MainObject; Plugin_Objektname: SmartPartCompressed; Version: 1.1; Abstand_Öffn_Unten: 1.625 m; ash T_Feuchtebeständigkeit: nein; Feuerwiderstandsklasse~: nein
WV 1.1 | H2 Ebene 0 |  | 1113Sma0814159565 |  | VUK1 - Lichtleiste (ELT) | St | Trockenbauarbeiten | SmartPart | WV 1.1 |  |  |  | 0.2 |  |  |  |  | - | AllplanAttributes - Text1: WA; UK: 0 m; OK: 0 m; V6: 0 m; V7: 0 m; V8: 0 m; V9: 0; Länge: 1.2 m; Dicke: 0.025 m; Höhe: 0.15 m; Programmversion: 3.1; Text3: 0; Plugin_Bezeichnung: MainObject; Plugin_Objektname: SmartPartCompressed; Version: 1.1; Abstand_Öffn_Unten: 1.625 m; ash T_Feuchtebeständigkeit: nein; Feuerwiderstandsklasse~: nein
WV 1.1 | H2 Ebene 0 |  | 1113Sma0814159730 |  | VUK1 - Lichtleiste (ELT) | St | Trockenbauarbeiten | SmartPart | WV 1.1 |  |  |  | 0.2 |  |  |  |  | - | AllplanAttributes - Text1: WA2001; UK: 0 m; OK: 0 m; V6: 0 m; V7: 0 m; V8: 0 m; V9: 0; Länge: 1.2 m; Dicke: 0.025 m; Höhe: 0.15 m; Programmversion: 3.1; Text3: 0; Plugin_Bezeichnung: MainObject; Plugin_Objektname: SmartPartCompressed; Version: 1.1; Abstand_Öffn_Unten: 1.625 m; ash T_Feuchtebeständigkeit: nein; Feuerwiderstandsklasse~: nein
WV 1.1 | H2 Ebene 0 |  | 1113Sma0814159743 |  | VUK1 - Lichtleiste (ELT) | St | Trockenbauarbeiten | SmartPart | WV 1.1 |  |  |  | 0.2 |  |  |  |  | - | AllplanAttributes - Text1: WA2001; UK: 0 m; OK: 0 m; V6: 0 m; V7: 0 m; V8: 0 m; V9: 0; Länge: 1.2 m; Dicke: 0.025 m; Höhe: 0.15 m; Programmversion: 3.1; Text3: 0; Plugin_Bezeichnung: MainObject; Plugin_Objektname: SmartPartCompressed; Version: 1.1; Abstand_Öffn_Unten: 1.625 m; ash T_Feuchtebeständigkeit: nein; Feuerwiderstandsklasse~: nein
WV 1.1 | H2 Ebene 0 |  | 1113Sma0814159756 |  | VUK1 - Lichtleiste (ELT) | St | Trockenbauarbeiten | SmartPart | WV 1.1 |  |  |  | 0.2 |  |  |  |  | - | AllplanAttributes - Text1: WA2001; UK: 0 m; OK: 0 m; V6: 0 m; V7: 0 m; V8: 0 m; V9: 0; Länge: 1.2 m; Dicke: 0.025 m; Höhe: 0.15 m; Programmversion: 3.1; Text3: 0; Plugin_Bezeichnung: MainObject; Plugin_Objektname: SmartPartCompressed; Version: 1.1; Abstand_Öffn_Unten: 1.625 m; ash T_Feuchtebeständigkeit: nein; Feuerwiderstandsklasse~: nein
WV 1.1 | H2 Ebene 0 |  | 1113Sma0814159769 |  | VUK1 - Lichtleiste (ELT) | St | Trockenbauarbeiten | SmartPart | WV 1.1 |  |  |  | 0.2 |  |  |  |  | - | AllplanAttributes - Text1: WA2001; UK: 0 m; OK: 0 m; V6: 0 m; V7: 0 m; V8: 0 m; V9: 0; Länge: 1.2 m; Dicke: 0.025 m; Höhe: 0.15 m; Programmversion: 3.1; Text3: 0; Plugin_Bezeichnung: MainObject; Plugin_Objektname: SmartPartCompressed; Version: 1.1; Abstand_Öffn_Unten: 1.625 m; ash T_Feuchtebeständigkeit: nein; Feuerwiderstandsklasse~: nein
WV 1.1 | H2 Ebene 0 |  | 1113Sma0814159782 |  | VUK1 - Lichtleiste (ELT) | St | Trockenbauarbeiten | SmartPart | WV 1.1 |  |  |  | 0.2 |  |  |  |  | - | AllplanAttributes - Text1: WA2001; UK: 0 m; OK: 0 m; V6: 0 m; V7: 0 m; V8: 0 m; V9: 0; Länge: 1.2 m; Dicke: 0.025 m; Höhe: 0.15 m; Programmversion: 3.1; Text3: 0; Plugin_Bezeichnung: MainObject; Plugin_Objektname: SmartPartCompressed; Version: 1.1; Abstand_Öffn_Unten: 1.625 m; ash T_Feuchtebeständigkeit: nein; Feuerwiderstandsklasse~: nein
WV 1.1 | H2 Ebene 0 |  | 1113Sma0814159795 |  | VUK1 - Lichtleiste (ELT) | St | Trockenbauarbeiten | SmartPart | WV 1.1 |  |  |  | 0.2 |  |  |  |  | - | AllplanAttributes - Text1: WA2001; UK: 0 m; OK: 0 m; V6: 0 m; V7: 0 m; V8: 0 m; V9: 0; Länge: 1.2 m; Dicke: 0.025 m; Höhe: 0.15 m; Programmversion: 3.1; Text3: 0; Plugin_Bezeichnung: MainObject; Plugin_Objektname: SmartPartCompressed; Version: 1.1; Abstand_Öffn_Unten: 1.625 m; ash T_Feuchtebeständigkeit: nein; Feuerwiderstandsklasse~: nein
WV 1.1 | H2 Ebene 0 |  | 1113Sma0814159808 |  | VUK1 - Lichtleiste (ELT) | St | Trockenbauarbeiten | SmartPart | WV 1.1 |  |  |  | 0.2 |  |  |  |  | - | AllplanAttributes - Text1: WA2003; UK: 0 m; OK: 0 m; V6: 0 m; V7: 0 m; V8: 0 m; V9: 0; Länge: 1.2 m; Dicke: 0.025 m; Höhe: 0.15 m; Programmversion: 3.1; Text3: 0; Plugin_Bezeichnung: MainObject; Plugin_Objektname: SmartPartCompressed; Version: 1.1; Abstand_Öffn_Unten: 1.625 m; ash T_Feuchtebeständigkeit: nein; Feuerwiderstandsklasse~: nein
WV 1.1 | H2 Ebene 0 |  | 1113Sma0814159821 |  | VUK1 - Lichtleiste (ELT) | St | Trockenbauarbeiten | SmartPart | WV 1.1 |  |  |  | 0.2 |  |  |  |  | - | AllplanAttributes - Text1: WA2003; UK: 0 m; OK: 0 m; V6: 0 m; V7: 0 m; V8: 0 m; V9: 0; Länge: 1.2 m; Dicke: 0.025 m; Höhe: 0.15 m; Programmversion: 3.1; Text3: 0; Plugin_Bezeichnung: MainObject; Plugin_Objektname: SmartPartCompressed; Version: 1.1; Abstand_Öffn_Unten: 1.625 m; ash T_Feuchtebeständigkeit: nein; Feuerwiderstandsklasse~: nein
WV 1.1 | H2 Ebene 0 |  | 1113Sma0814159834 |  | VUK1 - Lichtleiste (ELT) | St | Trockenbauarbeiten | SmartPart | WV 1.1 |  |  |  | 0.2 |  |  |  |  | - | AllplanAttributes - Text1: WA2004; V6: 0 m; V7: 0 m; V8: 0 m; V9: 0; Länge: 1.2 m; Dicke: 0.025 m; Höhe: 0.15 m; Programmversion: 3.1; Text3: 0; Plugin_Bezeichnung: MainObject; Plugin_Objektname: SmartPartCompressed; Version: 1.1; Abstand_Öffn_Unten: 1.625 m; ash T_Feuchtebeständigkeit: nein; Feuerwiderstandsklasse~: nein
WV 1.1 | H2 Ebene 0 |  | 1113Sma0814159847 |  | VUK1 - Lichtleiste (ELT) | St | Trockenbauarbeiten | SmartPart | WV 1.1 |  |  |  | 0.2 |  |  |  |  | - | AllplanAttributes - Text1: WA2004; UK: 0 m; OK: 0 m; V6: 0 m; V7: 0 m; V8: 0 m; V9: 0; Länge: 1.2 m; Dicke: 0.025 m; Höhe: 0.15 m; Programmversion: 3.1; Text3: 0; Plugin_Bezeichnung: MainObject; Plugin_Objektname: SmartPartCompressed; Version: 1.1; Abstand_Öffn_Unten: 1.625 m; ash T_Feuchtebeständigkeit: nein; Feuerwiderstandsklasse~: nein
WV 1.1 | H2 Ebene 0 |  | 1113Sma0814159860 |  | VUK1 - Lichtleiste (ELT) | St | Trockenbauarbeiten | SmartPart | WV 1.1 |  |  |  | 0.2 |  |  |  |  | - | AllplanAttributes - Text1: WA2002; V6: 0 m; V7: 0 m; V8: 0 m; V9: 0; Länge: 1.2 m; Dicke: 0.025 m; Höhe: 0.15 m; Programmversion: 3.1; Text3: 0; Plugin_Bezeichnung: MainObject; Plugin_Objektname: SmartPartCompressed; Version: 1.1; Abstand_Öffn_Unten: 1.625 m; ash T_Feuchtebeständigkeit: nein; Feuerwiderstandsklasse~: nein
WV 1.1 | H2 Ebene 0 |  | 1113Sma0814159873 |  | VUK1 - Lichtleiste (ELT) | St | Trockenbauarbeiten | SmartPart | WV 1.1 |  |  |  | 0.2 |  |  |  |  | - | AllplanAttributes - Text1: WA2010; UK: 0 m; OK: 0 m; V6: 0 m; V7: 0 m; V8: 0 m; V9: 0; Länge: 1.2 m; Dicke: 0.025 m; Höhe: 0.15 m; Programmversion: 3.1; Text3: 0; Plugin_Bezeichnung: MainObject; Plugin_Objektname: SmartPartCompressed; Version: 1.1; Abstand_Öffn_Unten: 1.625 m; ash T_Feuchtebeständigkeit: nein; Feuerwiderstandsklasse~: nein
WV 1.1 | H2 Ebene 0 |  | 1113Sma0814159886 |  | VUK1 - Lichtleiste (ELT) | St | Trockenbauarbeiten | SmartPart | WV 1.1 |  |  |  | 0.2 |  |  |  |  | - | AllplanAttributes - Text1: WA2010; UK: 0 m; OK: 0 m; V6: 0 m; V7: 0 m; V8: 0 m; V9: 0; Länge: 1.2 m; Dicke: 0.025 m; Höhe: 0.15 m; Programmversion: 3.1; Text3: 0; Plugin_Bezeichnung: MainObject; Plugin_Objektname: SmartPartCompressed; Version: 1.1; Abstand_Öffn_Unten: 1.625 m; ash T_Feuchtebeständigkeit: nein; Feuerwiderstandsklasse~: nein
WV 1.1 | H2 Ebene 0 |  | 1113Sma0814159899 |  | VUK1 - Lichtleiste (ELT) | St | Trockenbauarbeiten | SmartPart | WV 1.1 |  |  |  | 0.2 |  |  |  |  | - | AllplanAttributes - Text1: WA2001; UK: 0 m; OK: 0 m; V6: 0 m; V7: 0 m; V8: 0 m; V9: 0; Länge: 1.2 m; Dicke: 0.025 m; Höhe: 0.15 m; Programmversion: 3.1; Text3: 0; Plugin_Bezeichnung: MainObject; Plugin_Objektname: SmartPartCompressed; Version: 1.1; Abstand_Öffn_Unten: 1.625 m; ash T_Feuchtebeständigkeit: nein; Feuerwiderstandsklasse~: nein
WV 1.1 | H2 Ebene 0 |  | 1113Sma0814159901 |  | VUK1 - Lichtleiste (ELT) | St | Trockenbauarbeiten | SmartPart | WV 1.1 |  |  |  | 0.2 |  |  |  |  | - | AllplanAttributes - Text1: WA2001; UK: 0 m; OK: 0 m; V6: 0 m; V7: 0 m; V8: 0 m; V9: 0; Länge: 1.2 m; Dicke: 0.025 m; Höhe: 0.15 m; Programmversion: 3.1; Text3: 0; Plugin_Bezeichnung: MainObject; Plugin_Objektname: SmartPartCompressed; Version: 1.1; Abstand_Öffn_Unten: 1.625 m; ash T_Feuchtebeständigkeit: nein; Feuerwiderstandsklasse~: nein
WV 1.1 | H2 Ebene 0 |  | 1113Sma0814159903 |  | VUK1 - Lichtleiste (ELT) | St | Trockenbauarbeiten | SmartPart | WV 1.1 |  |  |  | 0.2 |  |  |  |  | - | AllplanAttributes - Text1: WA2001; UK: 0 m; OK: 0 m; V6: 0 m; V7: 0 m; V8: 0 m; V9: 0; Länge: 1.2 m; Dicke: 0.025 m; Höhe: 0.15 m; Programmversion: 3.1; Text3: 0; Plugin_Bezeichnung: MainObject; Plugin_Objektname: SmartPartCompressed; Version: 1.1; Abstand_Öffn_Unten: 1.625 m; ash T_Feuchtebeständigkeit: nein; Feuerwiderstandsklasse~: nein
WV 1.1 | H2 Ebene 0 |  | 1113Sma0814159905 |  | VUK1 - Lichtleiste (ELT) | St | Trockenbauarbeiten | SmartPart | WV 1.1 |  |  |  | 0.2 |  |  |  |  | - | AllplanAttributes - Text1: WA2001; UK: 0 m; OK: 0 m; V6: 0 m; V7: 0 m; V8: 0 m; V9: 0; Länge: 1.2 m; Dicke: 0.025 m; Höhe: 0.15 m; Programmversion: 3.1; Text3: 0; Plugin_Bezeichnung: MainObject; Plugin_Objektname: SmartPartCompressed; Version: 1.1; Abstand_Öffn_Unten: 1.625 m; ash T_Feuchtebeständigkeit: nein; Feuerwiderstandsklasse~: nein
WV 1.1 | H2 Ebene 0 |  | 1113Sma0814159907 |  | VUK1 - Lichtleiste (ELT) | St | Trockenbauarbeiten | SmartPart | WV 1.1 |  |  |  | 0.2 |  |  |  |  | - | AllplanAttributes - Text1: WA2001; UK: 0 m; OK: 0 m; V6: 0 m; V7: 0 m; V8: 0 m; V9: 0; Länge: 1.2 m; Dicke: 0.025 m; Höhe: 0.15 m; Programmversion: 3.1; Text3: 0; Plugin_Bezeichnung: MainObject; Plugin_Objektname: SmartPartCompressed; Version: 1.1; Abstand_Öffn_Unten: 1.625 m; ash T_Feuchtebeständigkeit: nein; Feuerwiderstandsklasse~: nein
WV 1.1 | H2 Ebene 0 |  | 1113Sma0814159909 |  | VUK1 - Lichtleiste (ELT) | St | Trockenbauarbeiten | SmartPart | WV 1.1 |  |  |  | 0.2 |  |  |  |  | - | AllplanAttributes - Text1: WA2001; UK: 0 m; OK: 0 m; V6: 0 m; V7: 0 m; V8: 0 m; V9: 0; Länge: 1.2 m; Dicke: 0.025 m; Höhe: 0.15 m; Programmversion: 3.1; Text3: 0; Plugin_Bezeichnung: MainObject; Plugin_Objektname: SmartPartCompressed; Version: 1.1; Abstand_Öffn_Unten: 1.625 m; ash T_Feuchtebeständigkeit: nein; Feuerwiderstandsklasse~: nein
WV 1.1 | H2 Ebene 0 |  | 1113Sma0814159911 |  | VUK1 - Lichtleiste (ELT) | St | Trockenbauarbeiten | SmartPart | WV 1.1 |  |  |  | 0.2 |  |  |  |  | - | AllplanAttributes - Text1: WA2001; UK: 0 m; OK: 0 m; V6: 0 m; V7: 0 m; V8: 0 m; V9: 0; Länge: 1.2 m; Dicke: 0.025 m; Höhe: 0.15 m; Programmversion: 3.1; Text3: 0; Plugin_Bezeichnung: MainObject; Plugin_Objektname: SmartPartCompressed; Version: 1.1; Abstand_Öffn_Unten: 1.625 m; ash T_Feuchtebeständigkeit: nein; Feuerwiderstandsklasse~: nein
WV 1.1 | H2 Ebene 0 |  | 1113Sma0814159913 |  | VUK1 - Lichtleiste (ELT) | St | Trockenbauarbeiten | SmartPart | WV 1.1 |  |  |  | 0.2 |  |  |  |  | - | AllplanAttributes - Text1: WA2001; UK: 0 m; OK: 0 m; V6: 0 m; V7: 0 m; V8: 0 m; V9: 0; Länge: 1.2 m; Dicke: 0.025 m; Höhe: 0.15 m; Programmversion: 3.1; Text3: 0; Plugin_Bezeichnung: MainObject; Plugin_Objektname: SmartPartCompressed; Version: 1.1; Abstand_Öffn_Unten: 1.625 m; ash T_Feuchtebeständigkeit: nein; Feuerwiderstandsklasse~: nein
WV 1.1 | H2 Ebene 0 |  | 1113Sma0814159915 |  | VUK1 - Lichtleiste (ELT) | St | Trockenbauarbeiten | SmartPart | WV 1.1 |  |  |  | 0.2 |  |  |  |  | - | AllplanAttributes - Text1: WA2001; UK: 0 m; OK: 0 m; V6: 0 m; V7: 0 m; V8: 0 m; V9: 0; Länge: 1.2 m; Dicke: 0.025 m; Höhe: 0.15 m; Programmversion: 3.1; Text3: 0; Plugin_Bezeichnung: MainObject; Plugin_Objektname: SmartPartCompressed; Version: 1.1; Abstand_Öffn_Unten: 1.625 m; ash T_Feuchtebeständigkeit: nein; Feuerwiderstandsklasse~: nein
WV 1.1 | H2 Ebene 0 |  | 1113Sma0814159917 |  | VUK1 - Lichtleiste (ELT) | St | Trockenbauarbeiten | SmartPart | WV 1.1 |  |  |  | 0.2 |  |  |  |  | - | AllplanAttributes - Text1: WA2001; UK: 0 m; OK: 0 m; V6: 0 m; V7: 0 m; V8: 0 m; V9: 0; Länge: 1.2 m; Dicke: 0.025 m; Höhe: 0.15 m; Programmversion: 3.1; Text3: 0; Plugin_Bezeichnung: MainObject; Plugin_Objektname: SmartPartCompressed; Version: 1.1; Abstand_Öffn_Unten: 1.625 m; ash T_Feuchtebeständigkeit: nein; Feuerwiderstandsklasse~: nein
WV 1.1 | H2 Ebene 0 |  | 1113Sma0814159919 |  | VUK1 - Lichtleiste (ELT) | St | Trockenbauarbeiten | SmartPart | WV 1.1 |  |  |  | 0.2 |  |  |  |  | - | AllplanAttributes - Text1: WA2001; UK: 0 m; OK: 0 m; V6: 0 m; V7: 0 m; V8: 0 m; V9: 0; Länge: 1.2 m; Dicke: 0.025 m; Höhe: 0.15 m; Programmversion: 3.1; Text3: 0; Plugin_Bezeichnung: MainObject; Plugin_Objektname: SmartPartCompressed; Version: 1.1; Abstand_Öffn_Unten: 1.625 m; ash T_Feuchtebeständigkeit: nein; Feuerwiderstandsklasse~: nein
WV 1.1 | H2 Ebene 0 |  | 1113Sma0814159921 |  | VUK1 - Lichtleiste (ELT) | St | Trockenbauarbeiten | SmartPart | WV 1.1 |  |  |  | 0.2 |  |  |  |  | - | AllplanAttributes - Text1: WA2001; UK: 0 m; OK: 0 m; V6: 0 m; V7: 0 m; V8: 0 m; V9: 0; Länge: 1.2 m; Dicke: 0.025 m; Höhe: 0.15 m; Programmversion: 3.1; Text3: 0; Plugin_Bezeichnung: MainObject; Plugin_Objektname: SmartPartCompressed; Version: 1.1; Abstand_Öffn_Unten: 1.625 m; ash T_Feuchtebeständigkeit: nein; Feuerwiderstandsklasse~: nein
WV 1.1 | H2 Ebene 0 |  | 1113Sma0814159923 |  | VUK1 - Lichtleiste (ELT) | St | Trockenbauarbeiten | SmartPart | WV 1.1 |  |  |  | 0.2 |  |  |  |  | - | AllplanAttributes - Text1: WA2001; UK: 0 m; OK: 0 m; V6: 0 m; V7: 0 m; V8: 0 m; V9: 0; Länge: 1.2 m; Dicke: 0.025 m; Höhe: 0.15 m; Programmversion: 3.1; Text3: 0; Plugin_Bezeichnung: MainObject; Plugin_Objektname: SmartPartCompressed; Version: 1.1; Abstand_Öffn_Unten: 1.625 m; ash T_Feuchtebeständigkeit: nein; Feuerwiderstandsklasse~: nein
WV 1.1 | H2 Ebene 0 |  | 1113Sma0814160094 |  | VUK1 - Lichtleiste (ELT) | St | Trockenbauarbeiten | SmartPart | WV 1.1 |  |  |  | 0.2 |  |  |  |  | - | AllplanAttributes - Text1: WA2001; UK: 0 m; OK: 0 m; V6: 0 m; V7: 0 m; V8: 0 m; V9: 0; Länge: 1.2 m; Dicke: 0.025 m; Höhe: 0.15 m; Programmversion: 3.1; Text3: 0; Plugin_Bezeichnung: MainObject; Plugin_Objektname: SmartPartCompressed; Version: 1.1; Abstand_Öffn_Unten: 1.625 m; ash T_Feuchtebeständigkeit: nein; Feuerwiderstandsklasse~: nein
WV 1.1 | H2 Ebene 0 |  | 1113Sma0814160107 |  | VUK1 - Lichtleiste (ELT) | St | Trockenbauarbeiten | SmartPart | WV 1.1 |  |  |  | 0.2 |  |  |  |  | - | AllplanAttributes - Text1: WA2001; UK: 0 m; OK: 0 m; V6: 0 m; V7: 0 m; V8: 0 m; V9: 0; Länge: 1.2 m; Dicke: 0.025 m; Höhe: 0.15 m; Programmversion: 3.1; Text3: 0; Plugin_Bezeichnung: MainObject; Plugin_Objektname: SmartPartCompressed; Version: 1.1; Abstand_Öffn_Unten: 1.625 m; ash T_Feuchtebeständigkeit: nein; Feuerwiderstandsklasse~: nein
WV 1.1 | H2 Ebene 0 |  | 1113Sma0814160120 |  | VUK1 - Lichtleiste (ELT) | St | Trockenbauarbeiten | SmartPart | WV 1.1 |  |  |  | 0.2 |  |  |  |  | - | AllplanAttributes - Text1: WA2001; UK: 0 m; OK: 0 m; V6: 0 m; V7: 0 m; V8: 0 m; V9: 0; Länge: 1.2 m; Dicke: 0.025 m; Höhe: 0.15 m; Programmversion: 3.1; Text3: 0; Plugin_Bezeichnung: MainObject; Plugin_Objektname: SmartPartCompressed; Version: 1.1; Abstand_Öffn_Unten: 1.625 m; ash T_Feuchtebeständigkeit: nein; Feuerwiderstandsklasse~: nein
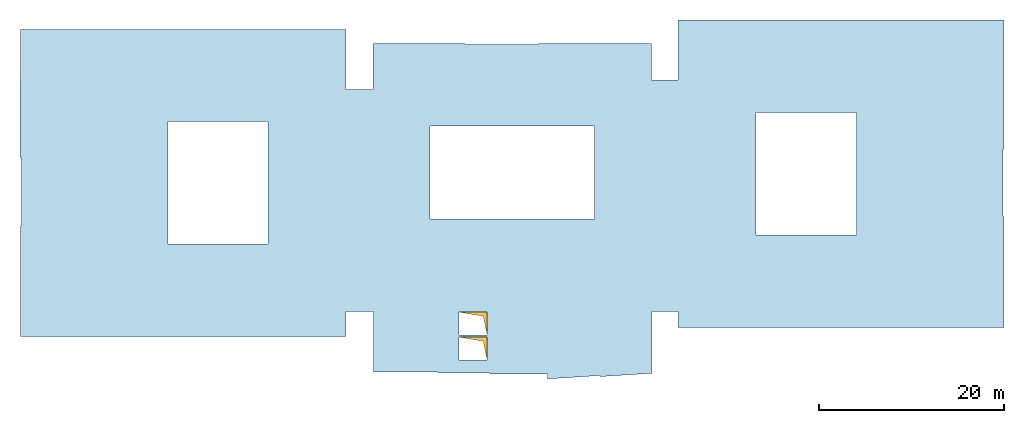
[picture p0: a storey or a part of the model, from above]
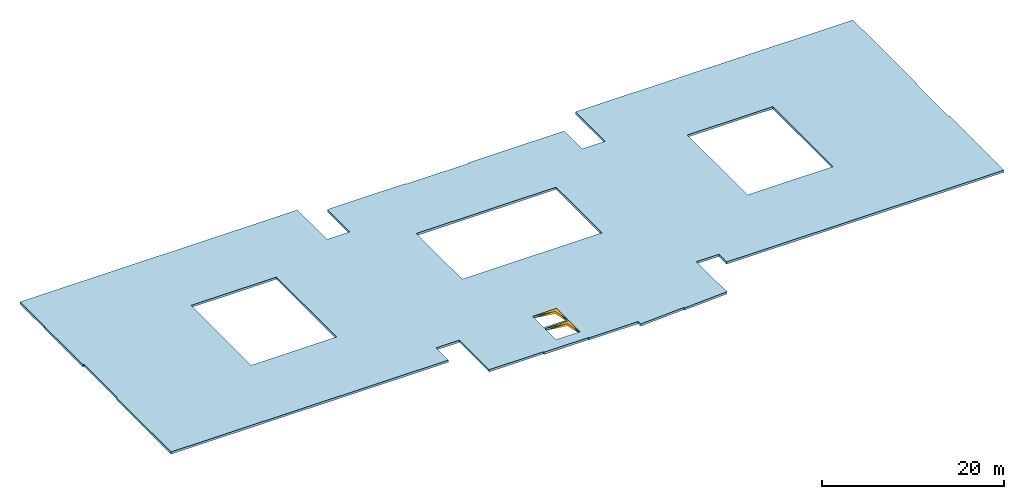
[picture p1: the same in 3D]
Properties of the parts of a building model (IFC4), part 73 of 80

# IfcWall (6826)
Name | In | Material | Allright_Bauteil_ID | 2D Interaktion | Codetext | Abrechnungsart | Gewerk | Objektname | Bezeichnung | AllplanAttributes, Material | Typ = SurfaceSpreadOfFlame | Brandschutzklasse | OKFF | P_ID | Status | LoadBearing | IsExternal | FireRating | ThermalTransmittance (W/K/m2) | Combustible | AcousticRating | Compartmentation | Reference
WV 1.1 | H2 Ebene 0 |  | 1113Sma0814160133 |  | VUK1 - Lichtleiste (ELT) | St | Trockenbauarbeiten | SmartPart | WV 1.1 |  |  |  | 0.2 |  |  |  |  | - | AllplanAttributes - Text1: WA2001; UK: 0 m; OK: 0 m; V6: 0 m; V7: 0 m; V8: 0 m; V9: 0; Länge: 1.2 m; Dicke: 0.025 m; Höhe: 0.15 m; Programmversion: 3.1; Text3: 0; Plugin_Bezeichnung: MainObject; Plugin_Objektname: SmartPartCompressed; Version: 1.1; Abstand_Öffn_Unten: 1.625 m; ash T_Feuchtebeständigkeit: nein; Feuerwiderstandsklasse~: nein
WV 1.1 | H2 Ebene 0 |  | 1113Sma0814160146 |  | VUK1 - Lichtleiste (ELT) | St | Trockenbauarbeiten | SmartPart | WV 1.1 |  |  |  | 0.2 |  |  |  |  | - | AllplanAttributes - Text1: WA2001; UK: 0 m; OK: 0 m; V6: 0 m; V7: 0 m; V8: 0 m; V9: 0; Länge: 1.2 m; Dicke: 0.025 m; Höhe: 0.15 m; Programmversion: 3.1; Text3: 0; Plugin_Bezeichnung: MainObject; Plugin_Objektname: SmartPartCompressed; Version: 1.1; Abstand_Öffn_Unten: 1.625 m; ash T_Feuchtebeständigkeit: nein; Feuerwiderstandsklasse~: nein
WV 1.1 | H2 Ebene 0 |  | 1113Sma0814160159 |  | VUK1 - Lichtleiste (ELT) | St | Trockenbauarbeiten | SmartPart | WV 1.1 |  |  |  | 0.2 |  |  |  |  | - | AllplanAttributes - Text1: WA2001; UK: 0 m; OK: 0 m; V6: 0 m; V7: 0 m; V8: 0 m; V9: 0; Länge: 1.2 m; Dicke: 0.025 m; Höhe: 0.15 m; Programmversion: 3.1; Text3: 0; Plugin_Bezeichnung: MainObject; Plugin_Objektname: SmartPartCompressed; Version: 1.1; Abstand_Öffn_Unten: 1.625 m; ash T_Feuchtebeständigkeit: nein; Feuerwiderstandsklasse~: nein
WV 1.1 | H2 Ebene 0 |  | 1113Sma0814160172 |  | VUK1 - Lichtleiste (ELT) | St | Trockenbauarbeiten | SmartPart | WV 1.1 |  |  |  | 0.2 |  |  |  |  | - | AllplanAttributes - Text1: WA2001; UK: 0 m; OK: 0 m; V6: 0 m; V7: 0 m; V8: 0 m; V9: 0; Länge: 1.2 m; Dicke: 0.025 m; Höhe: 0.15 m; Programmversion: 3.1; Text3: 0; Plugin_Bezeichnung: MainObject; Plugin_Objektname: SmartPartCompressed; Version: 1.1; Abstand_Öffn_Unten: 1.625 m; ash T_Feuchtebeständigkeit: nein; Feuerwiderstandsklasse~: nein
WV 1.1 | H2 Ebene 0 |  | 1113Sma0814160185 |  | VUK1 - Lichtleiste (ELT) | St | Trockenbauarbeiten | SmartPart | WV 1.1 |  |  |  | 0.2 |  |  |  |  | - | AllplanAttributes - Text1: WA2001; UK: 0 m; OK: 0 m; V6: 0 m; V7: 0 m; V8: 0 m; V9: 0; Länge: 1.2 m; Dicke: 0.025 m; Höhe: 0.15 m; Programmversion: 3.1; Text3: 0; Plugin_Bezeichnung: MainObject; Plugin_Objektname: SmartPartCompressed; Version: 1.1; Abstand_Öffn_Unten: 1.625 m; ash T_Feuchtebeständigkeit: nein; Feuerwiderstandsklasse~: nein
WV 1.1 | H2 Ebene 0 |  | 1113Sma0814160198 |  | VUK1 - Lichtleiste (ELT) | St | Trockenbauarbeiten | SmartPart | WV 1.1 |  |  |  | 0.2 |  |  |  |  | - | AllplanAttributes - Text1: WA2001; UK: 0 m; OK: 0 m; V6: 0 m; V7: 0 m; V8: 0 m; V9: 0; Länge: 1.2 m; Dicke: 0.025 m; Höhe: 0.15 m; Programmversion: 3.1; Text3: 0; Plugin_Bezeichnung: MainObject; Plugin_Objektname: SmartPartCompressed; Version: 1.1; Abstand_Öffn_Unten: 1.625 m; ash T_Feuchtebeständigkeit: nein; Feuerwiderstandsklasse~: nein
WV 1.1 | H2 Ebene 0 |  | 1113Sma0814160211 |  | VUK1 - Lichtleiste (ELT) | St | Trockenbauarbeiten | SmartPart | WV 1.1 |  |  |  | 0.2 |  |  |  |  | - | AllplanAttributes - Text1: WA2001; UK: 0 m; OK: 0 m; V6: 0 m; V7: 0 m; V8: 0 m; V9: 0; Länge: 1.2 m; Dicke: 0.025 m; Höhe: 0.15 m; Programmversion: 3.1; Text3: 0; Plugin_Bezeichnung: MainObject; Plugin_Objektname: SmartPartCompressed; Version: 1.1; Abstand_Öffn_Unten: 1.625 m; ash T_Feuchtebeständigkeit: nein; Feuerwiderstandsklasse~: nein
WV 1.1 | H2 Ebene 0 |  | 1113Sma0814160224 |  | VUK1 - Lichtleiste (ELT) | St | Trockenbauarbeiten | SmartPart | WV 1.1 |  |  |  | 0.2 |  |  |  |  | - | AllplanAttributes - Text1: WA2001; UK: 0 m; OK: 0 m; V6: 0 m; V7: 0 m; V8: 0 m; V9: 0; Länge: 1.2 m; Dicke: 0.025 m; Höhe: 0.15 m; Programmversion: 3.1; Text3: 0; Plugin_Bezeichnung: MainObject; Plugin_Objektname: SmartPartCompressed; Version: 1.1; Abstand_Öffn_Unten: 1.625 m; ash T_Feuchtebeständigkeit: nein; Feuerwiderstandsklasse~: nein
WV 1.1 | H2 Ebene 0 |  | 1113Sma0814160237 |  | VUK1 - Lichtleiste (ELT) | St | Trockenbauarbeiten | SmartPart | WV 1.1 |  |  |  | 0.2 |  |  |  |  | - | AllplanAttributes - Text1: WA2001; UK: 0 m; OK: 0 m; V6: 0 m; V7: 0 m; V8: 0 m; V9: 0; Länge: 1.2 m; Dicke: 0.025 m; Höhe: 0.15 m; Programmversion: 3.1; Text3: 0; Plugin_Bezeichnung: MainObject; Plugin_Objektname: SmartPartCompressed; Version: 1.1; Abstand_Öffn_Unten: 1.625 m; ash T_Feuchtebeständigkeit: nein; Feuerwiderstandsklasse~: nein
WV 1.1 | H2 Ebene 0 |  | 1113Sma0814160250 |  | VUK1 - Lichtleiste (ELT) | St | Trockenbauarbeiten | SmartPart | WV 1.1 |  |  |  | 0.2 |  |  |  |  | - | AllplanAttributes - Text1: WA2001; UK: 0 m; OK: 0 m; V6: 0 m; V7: 0 m; V8: 0 m; V9: 0; Länge: 1.2 m; Dicke: 0.025 m; Höhe: 0.15 m; Programmversion: 3.1; Text3: 0; Plugin_Bezeichnung: MainObject; Plugin_Objektname: SmartPartCompressed; Version: 1.1; Abstand_Öffn_Unten: 1.625 m; ash T_Feuchtebeständigkeit: nein; Feuerwiderstandsklasse~: nein
WV 1.1 | H2 Ebene 0 |  | 1113Sma0814160596 |  | VUK5 - Handlauf | St | Trockenbauarbeiten | SmartPart | WV 1.1 |  |  |  | 0.2 |  |  |  |  | - | AllplanAttributes - Text1: WA; UK: 0 m; OK: 0 m; V6: 0 m; V7: 0 m; V8: 0 m; V9: 0; Länge: 5.5 m; Dicke: 0.025 m; Höhe: 0.2 m; Programmversion: 3.1; Text3: 0; Plugin_Bezeichnung: MainObject; Plugin_Objektname: SmartPartCompressed; Version: 1.1; Abstand_Öffn_Unten: 0.9 m; ash T_Feuchtebeständigkeit: nein; Feuerwiderstandsklasse~: nein
WV 1.1 | H2 Ebene 0 |  | 1113Sma0814160623 |  | VUK5 - Handlauf | St | Trockenbauarbeiten | SmartPart | WV 1.1 |  |  |  | 0.2 |  |  |  |  | - | AllplanAttributes - Text1: WA; UK: 0 m; OK: 0 m; V6: 0 m; V7: 0 m; V8: 0 m; V9: 0; Länge: 1.5 m; Dicke: 0.025 m; Höhe: 0.2 m; Programmversion: 3.1; Text3: 0; Plugin_Bezeichnung: MainObject; Plugin_Objektname: SmartPartCompressed; Version: 1.1; Abstand_Öffn_Unten: 0.9 m; ash T_Feuchtebeständigkeit: nein; Feuerwiderstandsklasse~: nein
WV 1.1 | H2 Ebene 0 |  | 1113Sma0814160649 |  | VUK5 - Handlauf | St | Trockenbauarbeiten | SmartPart | WV 1.1 |  |  |  | 0.2 |  |  |  |  | - | AllplanAttributes - Text1: WA; UK: 0 m; OK: 0 m; V6: 0 m; V7: 0 m; V8: 0 m; V9: 0; Länge: 1.5 m; Dicke: 0.025 m; Höhe: 0.2 m; Programmversion: 3.1; Text3: 0; Plugin_Bezeichnung: MainObject; Plugin_Objektname: SmartPartCompressed; Version: 1.1; Abstand_Öffn_Unten: 0.9 m; ash T_Feuchtebeständigkeit: nein; Feuerwiderstandsklasse~: nein
WV 1.1 | H2 Ebene 0 |  | 1113Sma0814160663 |  | VUK5 - Handlauf | St | Trockenbauarbeiten | SmartPart | WV 1.1 |  |  |  | 0.2 |  |  |  |  | - | AllplanAttributes - Text1: WA; UK: 0 m; OK: 0 m; V6: 0 m; V7: 0 m; V8: 0 m; V9: 0; Länge: 5.4 m; Dicke: 0.025 m; Höhe: 0.2 m; Programmversion: 3.1; Text3: 0; Plugin_Bezeichnung: MainObject; Plugin_Objektname: SmartPartCompressed; Version: 1.1; Abstand_Öffn_Unten: 0.9 m; ash T_Feuchtebeständigkeit: nein; Feuerwiderstandsklasse~: nein
WV 1.1 | H2 Ebene 0 |  | 1113Sma0814160677 |  | VUK5 - Handlauf | St | Trockenbauarbeiten | SmartPart | WV 1.1 |  |  |  | 0.2 |  |  |  |  | - | AllplanAttributes - Text1: WA; UK: 0 m; OK: 0 m; V6: 0 m; V7: 0 m; V8: 0 m; V9: 0; Länge: 0.7 m; Dicke: 0.025 m; Höhe: 0.2 m; Programmversion: 3.1; Text3: 0; Plugin_Bezeichnung: MainObject; Plugin_Objektname: SmartPartCompressed; Version: 1.1; Abstand_Öffn_Unten: 0.9 m; ash T_Feuchtebeständigkeit: nein; Feuerwiderstandsklasse~: nein
WV 1.1 | H2 Ebene 0 |  | 1113Sma0814160691 |  | VUK1 - Feuerlöscher | St | Trockenbauarbeiten | SmartPart | WV 1.1 |  |  |  | 0.2 |  |  |  |  | - | AllplanAttributes - Text1: WA; UK: 0 m; OK: 0 m; V6: 0 m; V7: 0 m; V8: 0 m; V9: 0; Länge: 0.3 m; Dicke: 0.025 m; Höhe: 0.7 m; Programmversion: 3.1; Text3: 0; Plugin_Bezeichnung: MainObject; Plugin_Objektname: SmartPartCompressed; Version: 1.1; Abstand_Öffn_Unten: 0.85 m; ash T_Feuchtebeständigkeit: nein; Feuerwiderstandsklasse~: nein
WV 1.1 | H2 Ebene 0 |  | 1113Sma0814160719 |  | VUK1 - Feuerlöscher | St | Trockenbauarbeiten | SmartPart | WV 1.1 |  |  |  | 0.2 |  |  |  |  | - | AllplanAttributes - Text1: WA; UK: 0 m; OK: 0 m; V6: 0 m; V7: 0 m; V8: 0 m; V9: 0; Länge: 0.3 m; Dicke: 0.025 m; Höhe: 0.7 m; Programmversion: 3.1; Text3: 0; Plugin_Bezeichnung: MainObject; Plugin_Objektname: SmartPartCompressed; Version: 1.1; Abstand_Öffn_Unten: 0.85 m; ash T_Feuchtebeständigkeit: nein; Feuerwiderstandsklasse~: nein
WV 1.1 | H2 Ebene 0 |  | 1113Sma0814160761 |  | VUK1 - Feuerlöscher | St | Trockenbauarbeiten | SmartPart | WV 1.1 |  |  |  | 0.2 |  |  |  |  | - | AllplanAttributes - Text1: WA; UK: 0 m; OK: 0 m; V6: 0 m; V7: 0 m; V8: 0 m; V9: 0; Länge: 0.3 m; Dicke: 0.025 m; Höhe: 0.7 m; Programmversion: 3.1; Text3: 0; Plugin_Bezeichnung: MainObject; Plugin_Objektname: SmartPartCompressed; Version: 1.1; Abstand_Öffn_Unten: 0.85 m; ash T_Feuchtebeständigkeit: nein; Feuerwiderstandsklasse~: nein
WV 1.1 | H2 Ebene 0 |  | 1113Sma0814160775 |  | VUK1 - Feuerlöscher | St | Trockenbauarbeiten | SmartPart | WV 1.1 |  |  |  | 0.2 |  |  |  |  | - | AllplanAttributes - Text1: WA; UK: 0 m; OK: 0 m; V6: 0 m; V7: 0 m; V8: 0 m; V9: 0; Länge: 0.3 m; Dicke: 0.025 m; Höhe: 0.7 m; Programmversion: 3.1; Text3: 0; Plugin_Bezeichnung: MainObject; Plugin_Objektname: SmartPartCompressed; Version: 1.1; Abstand_Öffn_Unten: 0.85 m; ash T_Feuchtebeständigkeit: nein; Feuerwiderstandsklasse~: nein
WV 1.1 | H2 Ebene 0 |  | 1113Sma0814159227 |  | VUK1 - Hängeschrank | St | Trockenbauarbeiten | SmartPart | WV 1.1 |  |  |  | 0.2 |  |  |  |  | - | AllplanAttributes - Text1: WA2012; UK: 0 m; OK: 0 m; V6: 0 m; V7: 0 m; V8: 0 m; V9: 0; Länge: 2.48 m; Dicke: 0.025 m; Höhe: 0.2 m; Programmversion: 3.1; Text3: 0; Plugin_Bezeichnung: MainObject; Plugin_Objektname: SmartPartCompressed; Version: 1.1; Abstand_Öffn_Unten: 2.35 m; ash T_Feuchtebeständigkeit: nein; Feuerwiderstandsklasse~: nein
WV 1.1 | H2 Ebene 0 |  | 1113Sma0814159418 |  | VUK1 - Seifenspender | St | Trockenbauarbeiten | SmartPart | WV 1.1 |  |  |  | 0.2 |  |  |  |  | - | AllplanAttributes - Text1: WA2016; UK: 0 m; OK: 0 m; V6: 0 m; V7: 0 m; V8: 0 m; V9: 0; Länge: 0.2 m; Dicke: 0.025 m; Höhe: 0.3 m; Programmversion: 3.1; Text3: 0; Plugin_Bezeichnung: MainObject; Plugin_Objektname: SmartPartCompressed; Version: 1.1; Abstand_Öffn_Unten: 1.26 m; ash T_Feuchtebeständigkeit: nein; Feuerwiderstandsklasse~: nein
WV 1.1 | H2 Ebene 0 |  | 1113Sma0814160733 |  | VUK1 - Feuerlöscher | St | Trockenbauarbeiten | SmartPart | WV 1.1 |  |  |  | 0.2 |  |  |  |  | - | AllplanAttributes - Text1: WA; UK: 0 m; OK: 0 m; V6: 0 m; V7: 0 m; V8: 0 m; V9: 0; Länge: 0.3 m; Dicke: 0.025 m; Höhe: 0.7 m; Programmversion: 3.1; Text3: 0; Plugin_Bezeichnung: MainObject; Plugin_Objektname: SmartPartCompressed; Version: 1.1; Abstand_Öffn_Unten: 0.85 m; ash T_Feuchtebeständigkeit: nein; Feuerwiderstandsklasse~: nein
WV 1.1 | H2 Ebene 0 |  | 1113Sma0814160705 |  | VUK1 - Feuerlöscher | St | Trockenbauarbeiten | SmartPart | WV 1.1 |  |  |  | 0.2 |  |  |  |  | - | AllplanAttributes - Text1: WA; UK: 0 m; OK: 0 m; V6: 0 m; V7: 0 m; V8: 0 m; V9: 0; Länge: 0.3 m; Dicke: 0.025 m; Höhe: 0.7 m; Programmversion: 3.1; Text3: 0; Plugin_Bezeichnung: MainObject; Plugin_Objektname: SmartPartCompressed; Version: 1.1; Abstand_Öffn_Unten: 0.85 m; ash T_Feuchtebeständigkeit: nein; Feuerwiderstandsklasse~: nein
WV 1.1 | H2 Ebene 0 |  | 1113Sma0814160514 |  | VUK2 - ELT | St | Trockenbauarbeiten | SmartPart | WV 1.1 |  |  |  | 0.2 |  |  |  |  | - | AllplanAttributes - Text1: WA; UK: 0 m; OK: 0 m; V6: 0 m; V7: 0 m; V8: 0 m; V9: 0; Länge: 0.35 m; Dicke: 0.018 m; Höhe: 0.3 m; Programmversion: 3.1; Text3: 0; Plugin_Bezeichnung: MainObject; Plugin_Objektname: SmartPartCompressed; Version: 1.1; Abstand_Öffn_Unten: 1.6 m; ash T_Feuchtebeständigkeit: nein; Feuerwiderstandsklasse~: nein
WV 1.1 | H2 Ebene 0 |  | 1113Sma0814160541 |  | VUK2 - ELT | St | Trockenbauarbeiten | SmartPart | WV 1.1 |  |  |  | 0.2 |  |  |  |  | - | AllplanAttributes - Text1: WA; UK: 0 m; OK: 0 m; V6: 0 m; V7: 0 m; V8: 0 m; V9: 0; Länge: 0.74 m; Dicke: 0.018 m; Höhe: 0.3 m; Programmversion: 3.1; Text3: 0; Plugin_Bezeichnung: MainObject; Plugin_Objektname: SmartPartCompressed; Version: 1.1; Abstand_Öffn_Unten: 1.6 m; ash T_Feuchtebeständigkeit: nein; Feuerwiderstandsklasse~: nein
WV 1.1 | H2 Ebene 0 |  | 1113Sma0814160555 |  | VUK2 - ELT | St | Trockenbauarbeiten | SmartPart | WV 1.1 |  |  |  | 0.2 |  |  |  |  | - | AllplanAttributes - Text1: WA; UK: 0 m; OK: 0 m; V6: 0 m; V7: 0 m; V8: 0 m; V9: 0; Länge: 0.5 m; Dicke: 0.018 m; Höhe: 0.3 m; Programmversion: 3.1; Text3: 0; Plugin_Bezeichnung: MainObject; Plugin_Objektname: SmartPartCompressed; Version: 1.1; Abstand_Öffn_Unten: 1.6 m; ash T_Feuchtebeständigkeit: nein; Feuerwiderstandsklasse~: nein
WV 1.1 | H2 Ebene 0 |  | 1113Sma0814160582 |  | VUK2 - ELT | St | Trockenbauarbeiten | SmartPart | WV 1.1 |  |  |  | 0.2 |  |  |  |  | - | AllplanAttributes - Text1: WA; UK: 0 m; OK: 0 m; V6: 0 m; V7: 0 m; V8: 0 m; V9: 0; Länge: 0.59 m; Dicke: 0.018 m; Höhe: 0.3 m; Programmversion: 3.1; Text3: 0; Plugin_Bezeichnung: MainObject; Plugin_Objektname: SmartPartCompressed; Version: 1.1; Abstand_Öffn_Unten: 1.6 m; ash T_Feuchtebeständigkeit: nein; Feuerwiderstandsklasse~: nein
WV 1.1 | H2 Ebene 0 |  | 1113Sma0814161584 |  | VUK2 - ELT | St | Trockenbauarbeiten | SmartPart | WV 1.1 |  |  |  | 0.2 |  |  |  |  | - | AllplanAttributes - Text1: WA; V6: 0 m; V7: 0 m; V8: 0 m; V9: 0; Länge: 2.82 m; Dicke: 0.018 m; Höhe: 0.3 m; Programmversion: 3.1; Text3: 0; Plugin_Bezeichnung: MainObject; Plugin_Objektname: SmartPartCompressed; Version: 1.1; Abstand_Öffn_Unten: 1.6 m; ash T_Feuchtebeständigkeit: nein; Feuerwiderstandsklasse~: nein
WV 1.1 | H2 Ebene 0 |  | 1113Sma0814161607 |  | VUK2 - ELT | St | Trockenbauarbeiten | SmartPart | WV 1.1 |  |  |  | 0.2 |  |  |  |  | - | AllplanAttributes - Text1: WA; UK: 0 m; OK: 0 m; V6: 0 m; V7: 0 m; V8: 0 m; V9: 0; Länge: 2.82 m; Dicke: 0.018 m; Höhe: 0.3 m; Programmversion: 3.1; Text3: 0; Plugin_Bezeichnung: MainObject; Plugin_Objektname: SmartPartCompressed; Version: 1.1; Abstand_Öffn_Unten: 1.6 m; ash T_Feuchtebeständigkeit: nein; Feuerwiderstandsklasse~: nein
WV 1.1 | H2 Ebene 0 |  | 1113Sma0814161630 |  | VUK2 - ELT | St | Trockenbauarbeiten | SmartPart | WV 1.1 |  |  |  | 0.2 |  |  |  |  | - | AllplanAttributes - Text1: WA; V6: 0 m; V7: 0 m; V8: 0 m; V9: 0; Länge: 2.82 m; Dicke: 0.018 m; Höhe: 0.3 m; Programmversion: 3.1; Text3: 0; Plugin_Bezeichnung: MainObject; Plugin_Objektname: SmartPartCompressed; Version: 1.1; Abstand_Öffn_Unten: 1.6 m; ash T_Feuchtebeständigkeit: nein; Feuerwiderstandsklasse~: nein
WV 1.1 | H2 Ebene 0 |  | 1113Sma0814160451 |  | VUK2 - ELT | St | Trockenbauarbeiten | SmartPart | WV 1.1 |  |  |  | 0.2 |  |  |  |  | - | AllplanAttributes - Text1: WA; UK: 0 m; OK: 0 m; V6: 0 m; V7: 0 m; V8: 0 m; V9: 0; Länge: 2.82 m; Dicke: 0.018 m; Höhe: 0.3 m; Programmversion: 3.1; Text3: 0; Plugin_Bezeichnung: MainObject; Plugin_Objektname: SmartPartCompressed; Version: 1.1; Abstand_Öffn_Unten: 1.6 m; ash T_Feuchtebeständigkeit: nein; Feuerwiderstandsklasse~: nein
WV 1.1 | H2 Ebene 0 |  | 1113Sma0814161805 |  | VUK2 - ELT | St | Trockenbauarbeiten | SmartPart | WV 1.1 |  |  |  | 0.2 |  |  |  |  | - | AllplanAttributes - Text1: WA; UK: 0 m; OK: 0 m; V6: 0 m; V7: 0 m; V8: 0 m; V9: 0; Länge: 2.82 m; Dicke: 0.018 m; Höhe: 0.3 m; Programmversion: 3.1; Text3: 0; Plugin_Bezeichnung: MainObject; Plugin_Objektname: SmartPartCompressed; Version: 1.1; Abstand_Öffn_Unten: 2.4 m; ash T_Feuchtebeständigkeit: nein; Feuerwiderstandsklasse~: nein
WV 1.1 | H2 Ebene 0 |  | 1113Sma0814161828 |  | VUK2 - ELT | St | Trockenbauarbeiten | SmartPart | WV 1.1 |  |  |  | 0.2 |  |  |  |  | - | AllplanAttributes - Text1: WA; V6: 0 m; V7: 0 m; V8: 0 m; V9: 0; Länge: 2.82 m; Dicke: 0.018 m; Höhe: 0.3 m; Programmversion: 3.1; Text3: 0; Plugin_Bezeichnung: MainObject; Plugin_Objektname: SmartPartCompressed; Version: 1.1; Abstand_Öffn_Unten: 2.4 m; ash T_Feuchtebeständigkeit: nein; Feuerwiderstandsklasse~: nein
WV 1.1 | H2 Ebene 0 |  | 1113Sma0814161727 |  | VUK2 - ELT | St | Trockenbauarbeiten | SmartPart | WV 1.1 |  |  |  | 0.2 |  |  |  |  | - | AllplanAttributes - Text1: WA; V6: 0 m; V7: 0 m; V8: 0 m; V9: 0; Länge: 2.82 m; Dicke: 0.018 m; Höhe: 0.3 m; Programmversion: 3.1; Text3: 0; Plugin_Bezeichnung: MainObject; Plugin_Objektname: SmartPartCompressed; Version: 1.1; Abstand_Öffn_Unten: 2.4 m; ash T_Feuchtebeständigkeit: nein; Feuerwiderstandsklasse~: nein
WV 1.1 | H2 Ebene 0 |  | 1113Sma0814162010 |  | VUK2 - ELT | St | Trockenbauarbeiten | SmartPart | WV 1.1 |  |  |  | 0.2 |  |  |  |  | - | AllplanAttributes - Text1: WA; UK: 0 m; OK: 0 m; V6: 0 m; V7: 0 m; V8: 0 m; V9: 0; Länge: 0.59 m; Dicke: 0.018 m; Höhe: 0.3 m; Programmversion: 3.1; Text3: 0; Plugin_Bezeichnung: MainObject; Plugin_Objektname: SmartPartCompressed; Version: 1.1; Abstand_Öffn_Unten: 2.4 m; ash T_Feuchtebeständigkeit: nein; Feuerwiderstandsklasse~: nein
WV 1.1 | H2 Ebene 0 |  | 1113Sma0814161997 |  | VUK2 - ELT | St | Trockenbauarbeiten | SmartPart | WV 1.1 |  |  |  | 0.2 |  |  |  |  | - | AllplanAttributes - Text1: WA; UK: 0 m; OK: 0 m; V6: 0 m; V7: 0 m; V8: 0 m; V9: 0; Länge: 0.5 m; Dicke: 0.018 m; Höhe: 0.3 m; Programmversion: 3.1; Text3: 0; Plugin_Bezeichnung: MainObject; Plugin_Objektname: SmartPartCompressed; Version: 1.1; Abstand_Öffn_Unten: 2.4 m; ash T_Feuchtebeständigkeit: nein; Feuerwiderstandsklasse~: nein
WV 1.1 | H2 Ebene 0 |  | 1113Sma0814161984 |  | VUK2 - ELT | St | Trockenbauarbeiten | SmartPart | WV 1.1 |  |  |  | 0.2 |  |  |  |  | - | AllplanAttributes - Text1: WA; UK: 0 m; OK: 0 m; V6: 0 m; V7: 0 m; V8: 0 m; V9: 0; Länge: 0.74 m; Dicke: 0.018 m; Höhe: 0.3 m; Programmversion: 3.1; Text3: 0; Plugin_Bezeichnung: MainObject; Plugin_Objektname: SmartPartCompressed; Version: 1.1; Abstand_Öffn_Unten: 2.4 m; ash T_Feuchtebeständigkeit: nein; Feuerwiderstandsklasse~: nein
WV 1.1 | H2 Ebene 0 |  | 1113Sma0814162480 |  | VUK2 - ELT | St | Trockenbauarbeiten | SmartPart | WV 1.1 |  |  |  | 0.2 |  |  |  |  | - | AllplanAttributes - Text1: WA; V6: 0 m; V7: 0 m; V8: 0 m; V9: 0; Länge: 2.82 m; Dicke: 0.018 m; Höhe: 0.3 m; Programmversion: 3.1; Text3: 0; Plugin_Bezeichnung: MainObject; Plugin_Objektname: SmartPartCompressed; Version: 1.1; Abstand_Öffn_Unten: 1.6 m; ash T_Feuchtebeständigkeit: nein; Feuerwiderstandsklasse~: nein
WV 1.1 | H2 Ebene 0 |  | 1113Sma0814162493 |  | VUK2 - ELT | St | Trockenbauarbeiten | SmartPart | WV 1.1 |  |  |  | 0.2 |  |  |  |  | - | AllplanAttributes - Text1: WA; UK: 0 m; OK: 0 m; V6: 0 m; V7: 0 m; V8: 0 m; V9: 0; Länge: 2.82 m; Dicke: 0.018 m; Höhe: 0.3 m; Programmversion: 3.1; Text3: 0; Plugin_Bezeichnung: MainObject; Plugin_Objektname: SmartPartCompressed; Version: 1.1; Abstand_Öffn_Unten: 1.6 m; ash T_Feuchtebeständigkeit: nein; Feuerwiderstandsklasse~: nein
WV 1.1 | H2 Ebene 0 |  | 1113Sma0814162506 |  | VUK2 - ELT | St | Trockenbauarbeiten | SmartPart | WV 1.1 |  |  |  | 0.2 |  |  |  |  | - | AllplanAttributes - Text1: WA; V6: 0 m; V7: 0 m; V8: 0 m; V9: 0; Länge: 2.82 m; Dicke: 0.018 m; Höhe: 0.3 m; Programmversion: 3.1; Text3: 0; Plugin_Bezeichnung: MainObject; Plugin_Objektname: SmartPartCompressed; Version: 1.1; Abstand_Öffn_Unten: 1.6 m; ash T_Feuchtebeständigkeit: nein; Feuerwiderstandsklasse~: nein
WV 1.1 | H2 Ebene 0 |  | 1113Sma0814162519 |  | VUK2 - ELT | St | Trockenbauarbeiten | SmartPart | WV 1.1 |  |  |  | 0.2 |  |  |  |  | - | AllplanAttributes - Text1: WA; UK: 0 m; OK: 0 m; V6: 0 m; V7: 0 m; V8: 0 m; V9: 0; Länge: 2.82 m; Dicke: 0.018 m; Höhe: 0.3 m; Programmversion: 3.1; Text3: 0; Plugin_Bezeichnung: MainObject; Plugin_Objektname: SmartPartCompressed; Version: 1.1; Abstand_Öffn_Unten: 1.6 m; ash T_Feuchtebeständigkeit: nein; Feuerwiderstandsklasse~: nein
WV 1.1 | H2 Ebene 0 |  | 1113Sma0814162543 |  | VUK2 - ELT | St | Trockenbauarbeiten | SmartPart | WV 1.1 |  |  |  | 0.2 |  |  |  |  | - | AllplanAttributes - Text1: WA; UK: 0 m; OK: 0 m; V6: 0 m; V7: 0 m; V8: 0 m; V9: 0; Länge: 2.82 m; Dicke: 0.018 m; Höhe: 0.3 m; Programmversion: 3.1; Text3: 0; Plugin_Bezeichnung: MainObject; Plugin_Objektname: SmartPartCompressed; Version: 1.1; Abstand_Öffn_Unten: 2.4 m; ash T_Feuchtebeständigkeit: nein; Feuerwiderstandsklasse~: nein
WV 1.1 | H2 Ebene 0 |  | 1113Sma0814162556 |  | VUK2 - ELT | St | Trockenbauarbeiten | SmartPart | WV 1.1 |  |  |  | 0.2 |  |  |  |  | - | AllplanAttributes - Text1: WA; V6: 0 m; V7: 0 m; V8: 0 m; V9: 0; Länge: 2.82 m; Dicke: 0.018 m; Höhe: 0.3 m; Programmversion: 3.1; Text3: 0; Plugin_Bezeichnung: MainObject; Plugin_Objektname: SmartPartCompressed; Version: 1.1; Abstand_Öffn_Unten: 2.4 m; ash T_Feuchtebeständigkeit: nein; Feuerwiderstandsklasse~: nein
WV 1.1 | H2 Ebene 0 |  | 1113Sma0814162569 |  | VUK2 - ELT | St | Trockenbauarbeiten | SmartPart | WV 1.1 |  |  |  | 0.2 |  |  |  |  | - | AllplanAttributes - Text1: WA; V6: 0 m; V7: 0 m; V8: 0 m; V9: 0; Länge: 2.82 m; Dicke: 0.018 m; Höhe: 0.3 m; Programmversion: 3.1; Text3: 0; Plugin_Bezeichnung: MainObject; Plugin_Objektname: SmartPartCompressed; Version: 1.1; Abstand_Öffn_Unten: 2.4 m; ash T_Feuchtebeständigkeit: nein; Feuerwiderstandsklasse~: nein
WV 1.1 | H2 Ebene 0 |  | 1113Sma0814161782 |  | VUK2 - ELT | St | Trockenbauarbeiten | SmartPart | WV 1.1 |  |  |  | 0.2 |  |  |  |  | - | AllplanAttributes - Text1: WA; UK: 0 m; OK: 0 m; V6: 0 m; V7: 0 m; V8: 0 m; V9: 0; Länge: 2.82 m; Dicke: 0.018 m; Höhe: 0.3 m; Programmversion: 3.1; Text3: 0; Plugin_Bezeichnung: MainObject; Plugin_Objektname: SmartPartCompressed; Version: 1.1; Abstand_Öffn_Unten: 2.4 m; ash T_Feuchtebeständigkeit: nein; Feuerwiderstandsklasse~: nein
WV 1.1 | H2 Ebene 0 |  | 1113Sma0814161971 |  | VUK2 - ELT | St | Trockenbauarbeiten | SmartPart | WV 1.1 |  |  |  | 0.2 |  |  |  |  | - | AllplanAttributes - Text1: WA; UK: 0 m; OK: 0 m; V6: 0 m; V7: 0 m; V8: 0 m; V9: 0; Länge: 0.35 m; Dicke: 0.018 m; Höhe: 0.3 m; Programmversion: 3.1; Text3: 0; Plugin_Bezeichnung: MainObject; Plugin_Objektname: SmartPartCompressed; Version: 1.1; Abstand_Öffn_Unten: 2.4 m; ash T_Feuchtebeständigkeit: nein; Feuerwiderstandsklasse~: nein
WV 1.1 | H2 Ebene 0 |  | 1113Sma0814162420 |  | VUK2 - ELT | St | Trockenbauarbeiten | SmartPart | WV 1.1 |  |  |  | 0.2 |  |  |  |  | - | AllplanAttributes - Text1: WA; UK: 0 m; OK: 0 m; V6: 0 m; V7: 0 m; V8: 0 m; V9: 0; Länge: 0.59 m; Dicke: 0.018 m; Höhe: 0.3 m; Programmversion: 3.1; Text3: 0; Plugin_Bezeichnung: MainObject; Plugin_Objektname: SmartPartCompressed; Version: 1.1; Abstand_Öffn_Unten: 1.6 m; ash T_Feuchtebeständigkeit: nein; Feuerwiderstandsklasse~: nein
WV 1.1 | H2 Ebene 0 |  | 1113Sma0814162654 |  | VUK2 - ELT | St | Trockenbauarbeiten | SmartPart | WV 1.1 |  |  |  | 0.2 |  |  |  |  | - | AllplanAttributes - Text1: WA; UK: 0 m; OK: 0 m; V6: 0 m; V7: 0 m; V8: 0 m; V9: 0; Länge: 0.59 m; Dicke: 0.018 m; Höhe: 0.3 m; Programmversion: 3.1; Text3: 0; Plugin_Bezeichnung: MainObject; Plugin_Objektname: SmartPartCompressed; Version: 1.1; Abstand_Öffn_Unten: 2.4 m; ash T_Feuchtebeständigkeit: nein; Feuerwiderstandsklasse~: nein
WV 1.1 | H2 Ebene 0 |  | 1113Sma0814162441 |  | VUK2 - ELT | St | Trockenbauarbeiten | SmartPart | WV 1.1 |  |  |  | 0.2 |  |  |  |  | - | AllplanAttributes - Text1: WA; UK: 0 m; OK: 0 m; V6: 0 m; V7: 0 m; V8: 0 m; V9: 0; Länge: 0.5 m; Dicke: 0.018 m; Höhe: 0.3 m; Programmversion: 3.1; Text3: 0; Plugin_Bezeichnung: MainObject; Plugin_Objektname: SmartPartCompressed; Version: 1.1; Abstand_Öffn_Unten: 1.6 m; ash T_Feuchtebeständigkeit: nein; Feuerwiderstandsklasse~: nein
WV 1.1 | H2 Ebene 0 |  | 1113Sma0814162619 |  | VUK2 - ELT | St | Trockenbauarbeiten | SmartPart | WV 1.1 |  |  |  | 0.2 |  |  |  |  | - | AllplanAttributes - Text1: WA; UK: 0 m; OK: 0 m; V6: 0 m; V7: 0 m; V8: 0 m; V9: 0; Länge: 0.5 m; Dicke: 0.018 m; Höhe: 0.3 m; Programmversion: 3.1; Text3: 0; Plugin_Bezeichnung: MainObject; Plugin_Objektname: SmartPartCompressed; Version: 1.1; Abstand_Öffn_Unten: 2.4 m; ash T_Feuchtebeständigkeit: nein; Feuerwiderstandsklasse~: nein
WV 1.1 | H2 Ebene 0 |  | 1113Sma0814162454 |  | VUK2 - ELT | St | Trockenbauarbeiten | SmartPart | WV 1.1 |  |  |  | 0.2 |  |  |  |  | - | AllplanAttributes - Text1: WA; UK: 0 m; OK: 0 m; V6: 0 m; V7: 0 m; V8: 0 m; V9: 0; Länge: 0.59 m; Dicke: 0.018 m; Höhe: 0.3 m; Programmversion: 3.1; Text3: 0; Plugin_Bezeichnung: MainObject; Plugin_Objektname: SmartPartCompressed; Version: 1.1; Abstand_Öffn_Unten: 1.6 m; ash T_Feuchtebeständigkeit: nein; Feuerwiderstandsklasse~: nein
WV 1.1 | H2 Ebene 0 |  | 1113Sma0814162606 |  | VUK2 - ELT | St | Trockenbauarbeiten | SmartPart | WV 1.1 |  |  |  | 0.2 |  |  |  |  | - | AllplanAttributes - Text1: WA; UK: 0 m; OK: 0 m; V6: 0 m; V7: 0 m; V8: 0 m; V9: 0; Länge: 0.59 m; Dicke: 0.018 m; Höhe: 0.3 m; Programmversion: 3.1; Text3: 0; Plugin_Bezeichnung: MainObject; Plugin_Objektname: SmartPartCompressed; Version: 1.1; Abstand_Öffn_Unten: 2.4 m; ash T_Feuchtebeständigkeit: nein; Feuerwiderstandsklasse~: nein
WV 1.1 | H2 Ebene 0 |  | 1113Sma0814162467 |  | VUK2 - ELT | St | Trockenbauarbeiten | SmartPart | WV 1.1 |  |  |  | 0.2 |  |  |  |  | - | AllplanAttributes - Text1: WA; UK: 0 m; OK: 0 m; V6: 0 m; V7: 0 m; V8: 0 m; V9: 0; Länge: 0.5 m; Dicke: 0.018 m; Höhe: 0.3 m; Programmversion: 3.1; Text3: 0; Plugin_Bezeichnung: MainObject; Plugin_Objektname: SmartPartCompressed; Version: 1.1; Abstand_Öffn_Unten: 1.6 m; ash T_Feuchtebeständigkeit: nein; Feuerwiderstandsklasse~: nein
WV 1.1 | H2 Ebene 0 |  | 1113Sma0814162593 |  | VUK2 - ELT | St | Trockenbauarbeiten | SmartPart | WV 1.1 |  |  |  | 0.2 |  |  |  |  | - | AllplanAttributes - Text1: WA; UK: 0 m; OK: 0 m; V6: 0 m; V7: 0 m; V8: 0 m; V9: 0; Länge: 0.5 m; Dicke: 0.018 m; Höhe: 0.3 m; Programmversion: 3.1; Text3: 0; Plugin_Bezeichnung: MainObject; Plugin_Objektname: SmartPartCompressed; Version: 1.1; Abstand_Öffn_Unten: 2.4 m; ash T_Feuchtebeständigkeit: nein; Feuerwiderstandsklasse~: nein
WV 1.1 | H2 Ebene 0 |  | 1113Sma0814160422 |  | VUK2 - ELT | St | Trockenbauarbeiten | SmartPart | WV 1.1 |  |  |  | 0.2 |  |  |  |  | - | AllplanAttributes - Text1: WA; UK: 0 m; OK: 0 m; V6: 0 m; V7: 0 m; V8: 0 m; V9: 0; Länge: 2.92 m; Dicke: 0.018 m; Höhe: 0.3 m; Programmversion: 3.1; Text3: 0; Plugin_Bezeichnung: MainObject; Plugin_Objektname: SmartPartCompressed; Version: 1.1; Abstand_Öffn_Unten: 1.6 m; ash T_Feuchtebeständigkeit: nein; Feuerwiderstandsklasse~: nein
WV 1.1 | H2 Ebene 0 |  | 1113Sma0814163461 |  | VUK2 - ELT | St | Trockenbauarbeiten | SmartPart | WV 1.1 |  |  |  | 0.2 |  |  |  |  | - | AllplanAttributes - Text1: WA; UK: 0 m; OK: 0 m; V6: 0 m; V7: 0 m; V8: 0 m; V9: 0; Länge: 2.92 m; Dicke: 0.018 m; Höhe: 0.3 m; Programmversion: 3.1; Text3: 0; Plugin_Bezeichnung: MainObject; Plugin_Objektname: SmartPartCompressed; Version: 1.1; Abstand_Öffn_Unten: 2.4 m; ash T_Feuchtebeständigkeit: nein; Feuerwiderstandsklasse~: nein
WV 1.1 | H2 Ebene 0 |  | 1113Sma0814160437 |  | VUK2 - ELT | St | Trockenbauarbeiten | SmartPart | WV 1.1 |  |  |  | 0.2 |  |  |  |  | - | AllplanAttributes - Text1: WA; UK: 0 m; OK: 0 m; V6: 0 m; V7: 0 m; V8: 0 m; V9: 0; Länge: 2.92 m; Dicke: 0.018 m; Höhe: 0.3 m; Programmversion: 3.1; Text3: 0; Plugin_Bezeichnung: MainObject; Plugin_Objektname: SmartPartCompressed; Version: 1.1; Abstand_Öffn_Unten: 2.4 m; ash T_Feuchtebeständigkeit: nein; Feuerwiderstandsklasse~: nein
WV 1.1 | H2 Ebene 0 |  | 1113Sma0814164218 |  | VUK2 - ELT | St | Trockenbauarbeiten | SmartPart | WV 1.1 |  |  |  | 0.2 |  |  |  |  | - | AllplanAttributes - Text1: WA; UK: 0 m; OK: 0 m; V6: 0 m; V7: 0 m; V8: 0 m; V9: 0; Länge: 2.92 m; Dicke: 0.018 m; Höhe: 0.3 m; Programmversion: 3.1; Text3: 0; Plugin_Bezeichnung: MainObject; Plugin_Objektname: SmartPartCompressed; Version: 1.1; Abstand_Öffn_Unten: 1.6 m; ash T_Feuchtebeständigkeit: nein; Feuerwiderstandsklasse~: nein
WV 1.1 | H2 Ebene 0 |  | 1113Sma0814165134 |  | VUK1 - Stützgriff | St | Trockenbauarbeiten | SmartPart | WV 1.1 |  |  |  | 0.2 |  |  |  |  | - | AllplanAttributes - Text1: WA; UK: 0 m; OK: 0 m; V6: 0 m; V7: 0 m; V8: 0 m; V9: 0; Länge: 0.2 m; Dicke: 0.025 m; Höhe: 0.4 m; Programmversion: 3.1; Text3: 0; Plugin_Bezeichnung: MainObject; Plugin_Objektname: SmartPartCompressed; Version: 1.1; Abstand_Öffn_Unten: 0.63 m; ash T_Feuchtebeständigkeit: ja; Feuerwiderstandsklasse~: nein
WV 1.1 | H2 Ebene 0 |  | 1113Sma0814165159 |  | VUK1 - Stützgriff | St | Trockenbauarbeiten | SmartPart | WV 1.1 |  |  |  | 0.2 |  |  |  |  | - | AllplanAttributes - Text1: WA; UK: 0 m; OK: 0 m; V6: 0 m; V7: 0 m; V8: 0 m; V9: 0; Länge: 0.2 m; Dicke: 0.025 m; Höhe: 0.4 m; Programmversion: 3.1; Text3: 0; Plugin_Bezeichnung: MainObject; Plugin_Objektname: SmartPartCompressed; Version: 1.1; Abstand_Öffn_Unten: 0.63 m; ash T_Feuchtebeständigkeit: ja; Feuerwiderstandsklasse~: nein
WV 1.1 | H2 Ebene 0 |  | 1113Sma0814165173 |  | VUK1 - Stützgriff | St | Trockenbauarbeiten | SmartPart | WV 1.1 |  |  |  | 0.2 |  |  |  |  | - | AllplanAttributes - Text1: WA; UK: 0 m; OK: 0 m; V6: 0 m; V7: 0 m; V8: 0 m; V9: 0; Länge: 0.2 m; Dicke: 0.025 m; Höhe: 0.4 m; Programmversion: 3.1; Text3: 0; Plugin_Bezeichnung: MainObject; Plugin_Objektname: SmartPartCompressed; Version: 1.1; Abstand_Öffn_Unten: 0.63 m; ash T_Feuchtebeständigkeit: ja; Feuerwiderstandsklasse~: nein
WV 1.1 | H2 Ebene 0 |  | 1113Sma0814165175 |  | VUK1 - Stützgriff | St | Trockenbauarbeiten | SmartPart | WV 1.1 |  |  |  | 0.2 |  |  |  |  | - | AllplanAttributes - Text1: WA; UK: 0 m; OK: 0 m; V6: 0 m; V7: 0 m; V8: 0 m; V9: 0; Länge: 0.2 m; Dicke: 0.025 m; Höhe: 0.4 m; Programmversion: 3.1; Text3: 0; Plugin_Bezeichnung: MainObject; Plugin_Objektname: SmartPartCompressed; Version: 1.1; Abstand_Öffn_Unten: 0.63 m; ash T_Feuchtebeständigkeit: ja; Feuerwiderstandsklasse~: nein
WV 1.1 | H2 Ebene 0 |  | 1113Sma0814165085 |  | VUK1 - Kippspiegel | St | Trockenbauarbeiten | SmartPart | WV 1.1 |  |  |  | 0.2 |  |  |  |  | - | AllplanAttributes - Text1: WA; UK: 0 m; OK: 0 m; V6: 0 m; V7: 0 m; V8: 0 m; V9: 0; Länge: 0.6 m; Dicke: 0.025 m; Höhe: 0.35 m; Programmversion: 3.1; Text3: 0; Plugin_Bezeichnung: MainObject; Plugin_Objektname: SmartPartCompressed; Version: 1.1; Abstand_Öffn_Unten: 1.25 m; ash T_Feuchtebeständigkeit: ja; Feuerwiderstandsklasse~: nein
 | H2 Ebene 0 | WI-LB | 1113Wa 0812443609 |  |  | m² | Trockenbauarbeiten | Wand | Innenwand 1-Schalig | WI-LB |  |  | 0 | 1113HWa0812430768 |  |  |  | 0 |  |  | 0 | AllplanAttributes - Ortscode_Geschoßbezeichnung: E00; W_Deckenanschluss: Gleitender Deckenanschluss Fall 01; ash_W_Trockenbau_Qualitäten: 1b; Sicherheitsklasse: -
 | H2 Ebene 0 | WI-LB | 1113Wa 0812437641 |  |  | m² | Trockenbauarbeiten | Wand | Innenwand 1-Schalig | WI-LB |  |  | 0 | 1113HWa0812430724 |  |  |  | 0 |  |  | 0 | AllplanAttributes - Ortscode_Geschoßbezeichnung: E00; W_Deckenanschluss: Gleitender Deckenanschluss Fall 01; ash_W_Trockenbau_Qualitäten: 1b; Sicherheitsklasse: -
 | H2 Ebene 0 | Installationsraum | 1113Wa 0812437666 |  |  | m² | Trockenbauarbeiten | Wand |  |  |  |  | 0 | 1113HWa0812425826 |  |  |  | 0 |  |  | 0 | AllplanAttributes - Ortscode_Geschoßbezeichnung: E00; Sicherheitsklasse: -
 | H2 Ebene 0 | WI-VS | 1113Wa 0812437664 |  |  | m² | Trockenbauarbeiten | Wand |  |  |  |  | 0 | 1113HWa0812425826 |  |  |  | 0 |  |  | 0 | AllplanAttributes - Ortscode_Geschoßbezeichnung: E00; W_Deckenanschluss: Gleitender Deckenanschluss Fall 01; ash_W_Trockenbau_Qualitäten: 2; Sicherheitsklasse: -
 | H2 Ebene 0 | WI-LB | 1113Wa 0812444147 |  |  | m² | Trockenbauarbeiten | Wand | Innenwand 1-Schalig | WI-LB |  |  | 0 | 1113HWa0812444083 |  |  |  | 0 |  |  | 0 | AllplanAttributes - Ortscode_Geschoßbezeichnung: E00; W_Deckenanschluss: Gleitender Deckenanschluss Fall 01; ash_W_Trockenbau_Qualitäten: 1b; Sicherheitsklasse: -
 | H2 Ebene 0 | WI-LB | 1113Wa 0812444161 |  |  | m² | Trockenbauarbeiten | Wand | Innenwand 1-Schalig | WI-LB |  |  | 0 | 1113HWa0812444086 |  |  |  | 0 |  |  | 0 | AllplanAttributes - Ortscode_Geschoßbezeichnung: E00; W_Deckenanschluss: Gleitender Deckenanschluss Fall 01; ash_W_Trockenbau_Qualitäten: 1b; Sicherheitsklasse: -
 | H2 Ebene 0 | WI-STB | 1113Wa 0812442409 |  |  | m² | Zimmer- und Holzbauarbeiten | Wand | Innenwand 1-Schalig | WI-STB |  |  | 0 | 1113HWa0812429185 |  |  |  | 0 |  |  | 0 | AllplanAttributes - Ortscode_Geschoßbezeichnung: E00; Sicherheitsklasse: -
 | H2 Ebene 0 | WI-STB | 1113Wa 0812442412 |  |  | m² | Zimmer- und Holzbauarbeiten | Wand | Innenwand 1-Schalig | WI-STB |  |  | 0 | 1113HWa0812429187 |  |  |  | 0 |  |  | 0 | AllplanAttributes - Ortscode_Geschoßbezeichnung: E00; Sicherheitsklasse: -
 | H2 Ebene 0 | WI-LB | 1113Wa 0812549302 |  |  | m² | Trockenbauarbeiten | Wand | Innenwand 1-Schalig | WI-LB |  |  | 0 | 1113HWa0812549295 |  |  |  | 0 |  |  | 0 | AllplanAttributes - Ortscode_Geschoßbezeichnung: E00; W_Deckenanschluss: Gleitender Deckenanschluss Fall 01; ash_W_Trockenbau_Qualitäten: 1b; Sicherheitsklasse: -
 | H2 Ebene 0 | WI-LB | 1113Wa 0812549763 |  |  | m² | Trockenbauarbeiten | Wand | Außenwand 1-Schalig | WI-LB |  |  | 0 | 1113HWa0812549431 |  |  |  | 0 |  |  | 0 | AllplanAttributes - Ortscode_Geschoßbezeichnung: E00; W_Deckenanschluss: Gleitender Deckenanschluss Fall 01; ash_W_Trockenbau_Qualitäten: 1b; Sicherheitsklasse: -
 | H2 Ebene 0 | WA-STB | 1113Wa 0812437668 |  |  | m² | Zimmer- und Holzbauarbeiten | Wand | Außenwand 1-Schalig | WA-STB |  |  | 0 | 1113HWa0812425612 |  |  |  | 0 |  |  | 0 | AllplanAttributes - Ortscode_Geschoßbezeichnung: E00; Sicherheitsklasse: -
 | H2 Ebene 0 | WI-LB | 1113Wa 0812443678 |  |  | m² | Trockenbauarbeiten | Wand | Innenwand 1-Schalig | WI-LB |  |  | 0 | 1113HWa0812443477 |  |  |  | 0 |  |  | 0 | AllplanAttributes - Ortscode_Geschoßbezeichnung: E00; W_Deckenanschluss: Gleitender Deckenanschluss Fall 01; ash_W_Trockenbau_Qualitäten: 1b; Sicherheitsklasse: -
 | H2 Ebene 0 | WI-LB | 1113Wa 0812437362 |  |  | m² | Trockenbauarbeiten | Wand | Innenwand 1-Schalig | WI-LB |  |  | 0 | 1113HWa0812430757 |  |  |  | 0 |  |  | 0 | AllplanAttributes - Ortscode_Geschoßbezeichnung: E00; W_Deckenanschluss: Gleitender Deckenanschluss Fall 01; ash_W_Trockenbau_Qualitäten: 1b; Sicherheitsklasse: -
 | H2 Ebene 0 | WI-LB | 1113Wa 0812437390 |  |  | m² | Trockenbauarbeiten | Wand | Innenwand 1-Schalig | WI-LB |  |  | 0 | 1113HWa0812425633 |  |  |  | 0 |  |  | 0 | AllplanAttributes - Ortscode_Geschoßbezeichnung: E00; W_Deckenanschluss: Gleitender Deckenanschluss Fall 01; ash_W_Trockenbau_Qualitäten: 1b; Sicherheitsklasse: -
 | H2 Ebene 0 | WI-HW 60 | 1113Wa 0812437646 |  |  | m² | Zimmer- und Holzbauarbeiten | Wand | Innenwand 1-Schalig | WI-HW 60 |  |  | 0 | 1113HWa0812430721 |  |  |  | 0 |  |  | 0 | AllplanAttributes - Sicherheitsklasse: -
 | H2 Ebene 0 | WI-HW 60 | 1113Wa 0812655407 |  |  | m² | Zimmer- und Holzbauarbeiten | Wand | Innenwand 1-Schalig | WI-HW 60 |  |  | 0 | 1113HWa0812655397 |  |  |  | 0 |  |  | 0 | AllplanAttributes - Sicherheitsklasse: -
 | H2 Ebene 0 | WI-HW 60 | 1113Wa 0812437643 |  |  | m² | Zimmer- und Holzbauarbeiten | Wand | Innenwand 1-Schalig | WI-HW 60 |  |  | 0 | 1113HWa0812430720 |  |  |  | 0 |  |  | 0 | AllplanAttributes - Sicherheitsklasse: -
 | H2 Ebene 0 | WI-HW 60 | 1113Wa 0812437364 |  |  | m² | Zimmer- und Holzbauarbeiten | Wand | Innenwand 1-Schalig | WI-HW 60 |  |  | 0 | 1113HWa0812430730 |  |  |  | 0 |  |  | 0 | AllplanAttributes - Sicherheitsklasse: -
 | H2 Ebene 0 | WI-HW 60 | 1113Wa 0812437360 |  |  | m² | Zimmer- und Holzbauarbeiten | Wand | Innenwand 1-Schalig | WI-HW 60 |  |  | 0 | 1113HWa0812430755 |  |  |  | 0 |  |  | 0 | AllplanAttributes - Sicherheitsklasse: -
 | H2 Ebene 0 | WI-LB | 1113Wa 0812443009 |  |  | m² | Trockenbauarbeiten | Wand | Innenwand 1-Schalig | WI-LB |  |  | 0 | 1113HWa0812441874 |  |  |  | 0 |  |  | 0 | AllplanAttributes - Ortscode_Geschoßbezeichnung: E00; W_Deckenanschluss: Gleitender Deckenanschluss Fall 01; ash_W_Trockenbau_Qualitäten: 10b; Sicherheitsklasse: -
 | H2 Ebene 0 | WI-LB | 1113Wa 0812446036 |  |  | m² | Trockenbauarbeiten | Wand |  |  |  |  | 0 | 1113HWa0812445209 |  |  |  | 0 |  |  | 0 | AllplanAttributes - Ortscode_Geschoßbezeichnung: E00; W_Deckenanschluss: Gleitender Deckenanschluss Fall 03; ash_W_Trockenbau_Qualitäten: 10a; Sicherheitsklasse: -
 | H2 Ebene 0 | WI-LB | 1113Wa 0812446039 |  |  | m² | Trockenbauarbeiten | Wand |  |  |  |  | 0 | 1113HWa0812445223 |  |  |  | 0 |  |  | 0 | AllplanAttributes - Ortscode_Geschoßbezeichnung: E00; W_Deckenanschluss: Gleitender Deckenanschluss Fall 03; ash_W_Trockenbau_Qualitäten: 10a; Sicherheitsklasse: -
 | H2 Ebene 0 | WI-LB | 1113Wa 0812446042 |  |  | m² | Trockenbauarbeiten | Wand |  |  |  |  | 0 | 1113HWa0812445236 |  |  |  | 0 |  |  | 0 | AllplanAttributes - Ortscode_Geschoßbezeichnung: E00; W_Deckenanschluss: Gleitender Deckenanschluss Fall 03; ash_W_Trockenbau_Qualitäten: 10a; Sicherheitsklasse: -
 | H2 Ebene 0 | WI-LB | 1113Wa 0812446738 |  |  | m² | Trockenbauarbeiten | Wand |  |  |  |  | 0 | 1113HWa0812446710 |  |  |  | 0 |  |  | 0 | AllplanAttributes - Ortscode_Geschoßbezeichnung: E00; W_Deckenanschluss: Gleitender Deckenanschluss Fall 03; ash_W_Trockenbau_Qualitäten: 10a; Sicherheitsklasse: -
 | H2 Ebene 0 | WI-LB | 1113Wa 0812441668 |  |  | m² | Trockenbauarbeiten | Wand |  |  |  |  | 0 | 1113HWa0812440913 |  |  |  | 0 |  |  | 0 | AllplanAttributes - Ortscode_Geschoßbezeichnung: E00; W_Deckenanschluss: Gleitender Deckenanschluss Fall 03; ash_W_Trockenbau_Qualitäten: 10a; Sicherheitsklasse: -
 | H2 Ebene 0 | WI-LB | 1113Wa 0812442491 |  |  | m² | Trockenbauarbeiten | Wand |  |  |  |  | 0 | 1113HWa0812440946 |  |  |  | 0 |  |  | 0 | AllplanAttributes - Ortscode_Geschoßbezeichnung: E00; W_Deckenanschluss: Gleitender Deckenanschluss Fall 03; ash_W_Trockenbau_Qualitäten: 10a; Sicherheitsklasse: -
 | H2 Ebene 0 | WI-LB | 1113Wa 0812440263 |  |  | m² | Trockenbauarbeiten | Wand |  |  |  |  | 0 | 1113HWa0812440129 |  |  |  | 0 |  |  | 0 | AllplanAttributes - Ortscode_Geschoßbezeichnung: E00; W_Deckenanschluss: Gleitender Deckenanschluss Fall 03; ash_W_Trockenbau_Qualitäten: 10a; Sicherheitsklasse: -
 | H2 Ebene 0 | WI-LB | 1113Wa 0812440257 |  |  | m² | Trockenbauarbeiten | Wand |  |  |  |  | 0 | 1113HWa0812440130 |  |  |  | 0 |  |  | 0 | AllplanAttributes - Ortscode_Geschoßbezeichnung: E00; W_Deckenanschluss: Gleitender Deckenanschluss Fall 03; ash_W_Trockenbau_Qualitäten: 10a; Sicherheitsklasse: -
 | H2 Ebene 0 | WI-LB | 1113Wa 0812437366 |  |  | m² | Trockenbauarbeiten | Wand | Innenwand 1-Schalig | WI-LB |  |  | 0 | 1113HWa0812430731 |  |  |  | 0 |  |  | 0 | AllplanAttributes - Ortscode_Geschoßbezeichnung: E00; W_Deckenanschluss: Gleitender Deckenanschluss Fall 01; ash_W_Trockenbau_Qualitäten: 1b; Sicherheitsklasse: -
 | H2 Ebene 0 | WI-LB | 1113Wa 0812437721 |  |  | m² | Trockenbauarbeiten | Wand |  |  |  |  | 0 | 1113HWa0812425520 |  |  |  | 0 |  |  | 0 | AllplanAttributes - Ortscode_Geschoßbezeichnung: E00; W_Deckenanschluss: Gleitender Deckenanschluss Fall 03; ash_W_Trockenbau_Qualitäten: 10a; Sicherheitsklasse: -
 | H2 Ebene 0 | WI-LB | 1113Wa 0812438242 |  |  | m² | Trockenbauarbeiten | Wand |  |  |  |  | 0 | 1113HWa0812425521 |  |  |  | 0 |  |  | 0 | AllplanAttributes - Ortscode_Geschoßbezeichnung: E00; W_Deckenanschluss: Gleitender Deckenanschluss Fall 03; ash_W_Trockenbau_Qualitäten: 10a; Sicherheitsklasse: -
 | H2 Ebene 0 | WI-LB | 1113Wa 0812438254 |  |  | m² | Trockenbauarbeiten | Wand |  |  |  |  | 0 | 1113HWa0812425535 |  |  |  | 0 |  |  | 0 | AllplanAttributes - Ortscode_Geschoßbezeichnung: E00; W_Deckenanschluss: Gleitender Deckenanschluss Fall 03; ash_W_Trockenbau_Qualitäten: 10a; Sicherheitsklasse: -
 | H2 Ebene 0 | WI-LB | 1113Wa 0812437715 |  |  | m² | Trockenbauarbeiten | Wand |  |  |  |  | 0 | 1113HWa0812425540 |  |  |  | 0 |  |  | 0 | AllplanAttributes - Ortscode_Geschoßbezeichnung: E00; W_Deckenanschluss: Gleitender Deckenanschluss Fall 03; ash_W_Trockenbau_Qualitäten: 10a; Sicherheitsklasse: -
 | H2 Ebene 0 | WI-LB | 1113Wa 0812438258 |  |  | m² | Trockenbauarbeiten | Wand |  |  |  |  | 0 | 1113HWa0812425544 |  |  |  | 0 |  |  | 0 | AllplanAttributes - Ortscode_Geschoßbezeichnung: E00; W_Deckenanschluss: Gleitender Deckenanschluss Fall 03; ash_W_Trockenbau_Qualitäten: 10a; Sicherheitsklasse: -
 | H2 Ebene 0 | WI-LB | 1113Wa 0812438238 |  |  | m² | Trockenbauarbeiten | Wand |  |  |  |  | 0 | 1113HWa0812425553 |  |  |  | 0 |  |  | 0 | AllplanAttributes - Ortscode_Geschoßbezeichnung: E00; W_Deckenanschluss: Gleitender Deckenanschluss Fall 03; ash_W_Trockenbau_Qualitäten: 10a; Sicherheitsklasse: -
 | H2 Ebene 0 | WI-LB | 1113Wa 0812437717 |  |  | m² | Trockenbauarbeiten | Wand |  |  |  |  | 0 | 1113HWa0812425554 |  |  |  | 0 |  |  | 0 | AllplanAttributes - Ortscode_Geschoßbezeichnung: E00; W_Deckenanschluss: Gleitender Deckenanschluss Fall 03; ash_W_Trockenbau_Qualitäten: 10a; Sicherheitsklasse: -
 | H2 Ebene 0 | WI-LB | 1113Wa 0812438250 |  |  | m² | Trockenbauarbeiten | Wand |  |  |  |  | 0 | 1113HWa0812425584 |  |  |  | 0 |  |  | 0 | AllplanAttributes - Ortscode_Geschoßbezeichnung: E00; W_Deckenanschluss: Gleitender Deckenanschluss Fall 03; ash_W_Trockenbau_Qualitäten: 10a; Sicherheitsklasse: -
 | H2 Ebene 0 | WI-IW | 1113Wa 0812464612 |  |  | m² | Trockenbauarbeiten | Wand | Installationswand | WI-IW |  |  | 0 | 1113HWa0812464611 |  |  |  | 0 |  |  | 0 | AllplanAttributes - Ortscode_Geschoßbezeichnung: E00; W_Deckenanschluss: Gleitender Deckenanschluss Fall 01; ash_W_Trockenbau_Qualitäten: 18; Sicherheitsklasse: -
 | H2 Ebene 0 | WI-LB | 1113Wa 0812446900 |  |  | m² | Trockenbauarbeiten | Wand | Innenwand 1-Schalig | WI-LB |  |  | 0 | 1113HWa0812433353 |  |  |  | 0 |  |  | 0 | AllplanAttributes - Ortscode_Geschoßbezeichnung: E00; W_Deckenanschluss: Gleitender Deckenanschluss Fall 01; ash_W_Trockenbau_Qualitäten: 1b; Sicherheitsklasse: -
 | H2 Ebene 0 | WI-IW | 1113Wa 0812840219 | yes |  | m² | Trockenbauarbeiten | Wand | Innenwand 1-Schalig | WI-IW |  |  | 0 | 1113HWa0812840218 | NEW |  |  | 0 |  |  | 47 | AllplanAttributes - W_Deckenanschluss: Gleitender Deckenanschluss Fall 01; ash_W_Trockenbau_Qualitäten: 19; Sicherheitsklasse: -
 | H2 Ebene 0 | WI-IW | 1113Wa 0812840870 | yes |  | m² | Trockenbauarbeiten | Wand | Innenwand 1-Schalig | WI-IW |  |  | 0 | 1113HWa0812840869 | NEW |  |  | 0 |  |  | 47 | AllplanAttributes - W_Deckenanschluss: Gleitender Deckenanschluss Fall 01; ash_W_Trockenbau_Qualitäten: 9; Sicherheitsklasse: -
 | H2 Ebene 0 | WI-LB | 1113Wa 0812437332 |  |  | m² | Trockenbauarbeiten | Wand | Innenwand 1-Schalig | WI-LB |  |  | 0 | 1113HWa0812429063 |  |  |  | 0 | AllplanAttributes - Ortscode_Geschoßbezeichnung: E00; W_Deckenanschluss: Gleitender Deckenanschluss Fall 01; ash_W_Trockenbau_Qualitäten: 13; Sicherheitsklasse: -
 | H2 Ebene 0 | WI-LB | 1113Wa 0812544546 |  |  | m² | Trockenbauarbeiten | Wand | Innenwand 1-Schalig | WI-LB |  |  | 0 | 1113HWa0812544521 |  |  |  | 0 |  |  | 0 | AllplanAttributes - Ortscode_Geschoßbezeichnung: E00; W_Deckenanschluss: Gleitender Deckenanschluss Fall 01; ash_W_Trockenbau_Qualitäten: 13; Sicherheitsklasse: -
 | H2 Ebene 0 | WI-HW 60 | 1113Wa 0812443013 |  |  | m² | Zimmer- und Holzbauarbeiten | Wand | Innenwand 1-Schalig | WI-HW 60 |  |  | 0 | 1113HWa0812440742 |  |  |  | 0 |  |  | 0 | AllplanAttributes - Sicherheitsklasse: -
 | H2 Ebene 0 | Installationsraum | 1113Wa 0812446948 |  |  | m² | Trockenbauarbeiten | Wand |  |  |  |  | 0 | 1113HWa0812430885 |  |  |  | 0 |  |  | 0 | AllplanAttributes - Ortscode_Geschoßbezeichnung: E00; Sicherheitsklasse: -
 | H2 Ebene 0 | WI-VS | 1113Wa 0812446895 |  |  | m² | Trockenbauarbeiten | Wand |  |  |  |  | 0 | 1113HWa0812430885 |  |  |  | 0 |  |  | 0 | AllplanAttributes - Ortscode_Geschoßbezeichnung: E00; W_Deckenanschluss: Gleitender Deckenanschluss Fall 01; ash_W_Trockenbau_Qualitäten: 2; Sicherheitsklasse: -
 | H2 Ebene 0 | WI-IW | 1113Wa 0812437266 |  |  | m² | Trockenbauarbeiten | Wand | Installationswand | WI-IW |  |  | 0 | 1113HWa0812429077 |  |  |  | 0 |  |  | 0 | AllplanAttributes - W_Deckenanschluss: Gleitender Deckenanschluss Fall 01; ash_W_Trockenbau_Qualitäten: 11; Sicherheitsklasse: -
 | H2 Ebene 0 | Installationsraum | 1113Wa 0812437268 |  |  | m² | Trockenbauarbeiten | Wand | Installationswand | Installationsraum |  |  | 0 | 1113HWa0812429077 |  |  |  | 0 |  |  | 0 | AllplanAttributes - Sicherheitsklasse: -
 | H2 Ebene 0 | WI-IW | 1113Wa 0812437270 |  |  | m² | Trockenbauarbeiten | Wand | Installationswand | WI-IW |  |  | 0 | 1113HWa0812429077 |  |  |  | 0 |  |  | 0 | AllplanAttributes - W_Deckenanschluss: Gleitender Deckenanschluss Fall 01; ash_W_Trockenbau_Qualitäten: 11; Sicherheitsklasse: -
 | H2 Ebene 0 | WI-HW 60 | 1113Wa 0812439862 |  |  | m² | Zimmer- und Holzbauarbeiten | Wand | Innenwand 1-Schalig | WI-HW 60 |  |  | 0 | 1113HWa0812439858 |  |  |  | 0 | AllplanAttributes - Ortscode_Geschoßbezeichnung: E00; Sicherheitsklasse: -
 | H2 Ebene 0 | WI-HW 60 | 1113Wa 0812439829 |  |  | m² | Zimmer- und Holzbauarbeiten | Wand | Innenwand 1-Schalig | WI-HW 60 |  |  | 0 | 1113HWa0812439463 |  |  |  | 0 |  |  | 0 | AllplanAttributes - Sicherheitsklasse: -
 | H2 Ebene 0 | WI-LB | 1113Wa 0812742684 |  |  | m² | Trockenbauarbeiten | Wand | Innenwand 1-Schalig | WI-LB |  |  | 0 | 1113HWa0812742683 |  |  |  | 0 |  |  | 0 | AllplanAttributes - Ortscode_Geschoßbezeichnung: E00; W_Deckenanschluss: Gleitender Deckenanschluss Fall 01; ash_W_Trockenbau_Qualitäten: 1b; Sicherheitsklasse: -
 | H2 Ebene 0 | Installationsraum | 1113Wa 0812439605 |  |  | m² | Trockenbauarbeiten | Wand | Installationswand | Installationsraum |  |  | 0 | 1113HWa0812425593 |  |  |  | 0 |  |  | 0 | AllplanAttributes - Sicherheitsklasse: -
 | H2 Ebene 0 | WI-VS | 1113Wa 0812439611 |  |  | m² | Trockenbauarbeiten | Wand | Installationswand | WI-VS |  |  | 0 | 1113HWa0812425593 |  |  |  | 0 |  |  | 0 | AllplanAttributes - W_Deckenanschluss: Gleitender Deckenanschluss Fall 01; ash_W_Trockenbau_Qualitäten: 18; Sicherheitsklasse: -
 | H2 Ebene 0 | WI-HW 60 | 1113Wa 0812755727 |  |  | m² | Zimmer- und Holzbauarbeiten | Wand | Innenwand 1-Schalig | WI-HW 60 |  |  | 0 | 1113HWa0812755527 |  |  |  | 0 |  |  | 47 | AllplanAttributes - Sicherheitsklasse: -
 | H2 Ebene 0 | WI-LB | 1113Wa 0813445384 |  |  | m² | Trockenbauarbeiten | Wand | Innenwand 1-Schalig | WI-LB |  |  | 0 | 1113HWa0812755527 |  |  |  | 0 | AllplanAttributes - ash_W_Trockenbau_Qualitäten: 6; Sicherheitsklasse: -
 | H2 Ebene 0 | WI-LB | 1113Wa 0812447371 |  |  | m² | Trockenbauarbeiten | Wand | Innenwand 1-Schalig | WI-LB |  |  | 0 | 1113HWa0812429058 |  |  |  | 0 |  |  | 0 | AllplanAttributes - Ortscode_Geschoßbezeichnung: E00; W_Deckenanschluss: Gleitender Deckenanschluss Fall 01; ash_W_Trockenbau_Qualitäten: 1b; Sicherheitsklasse: -
 | H2 Ebene 0 | WI-STB | 1113Wa 0813453434 |  |  | m² | Zimmer- und Holzbauarbeiten | Wand | Innenwand 1-Schalig | WI-STB |  |  | 0 | 1113HWa0813453430 |  |  |  | 0 |  |  | 0 | AllplanAttributes - Sicherheitsklasse: -
 | H2 Ebene 0 | WI-HW 60 | 1113Wa 0813574524 |  |  | m² | Zimmer- und Holzbauarbeiten | Wand | Innenwand 1-Schalig | WI-HW 60 |  |  | 0 | 1113HWa0813574523 |  |  |  | 0 |  |  | 47 | AllplanAttributes - Sicherheitsklasse: -
 | H2 Ebene 0 | WI-IW | 1113Wa 0813047138 |  |  | m² | Trockenbauarbeiten | Wand | Installationswand | WI-IW |  |  | 0 | 1113HWa0813047137 |  |  |  | 0 |  |  | 52 | AllplanAttributes - W_Deckenanschluss: Gleitender Deckenanschluss Fall 01; Sicherheitsklasse: -
 | H2 Ebene 0 | WI-LB | 1113Wa 0813662772 |  |  | m² | Trockenbauarbeiten | Wand | Innenwand 1-Schalig | WI-LB |  |  | 0 | 1113HWa0813662760 |  |  |  | 0 |  |  | 47 | AllplanAttributes - ash_W_Trockenbau_Qualitäten: 8; Sicherheitsklasse: -
 | H2 Ebene 0 | Installationsraum | 1113Wa 0813662773 |  |  | m² | Trockenbauarbeiten | Wand | Innenwand 1-Schalig | Installationsraum |  |  | 0 | 1113HWa0813662760 |  |  |  | 0 |  |  | 47 | AllplanAttributes - Sicherheitsklasse: -
 | H2 Ebene 0 | WI-HW 60 | 1113Wa 0813662778 |  |  | m² | Zimmer- und Holzbauarbeiten | Wand | Innenwand 1-Schalig | WI-HW 60 |  |  | 0 | 1113HWa0813662760 |  |  |  | 0 |  |  | 47 | AllplanAttributes - Sicherheitsklasse: -
 | H2 Ebene 0 | Installationsraum | 1113Wa 0812437330 |  |  | m² | Trockenbauarbeiten | Wand | Installationswand | Installationsraum |  |  | 0 | 1113HWa0812432276 |  |  |  | 0 |  |  | 0 | AllplanAttributes - Sicherheitsklasse: -
 | H2 Ebene 0 | WI-VS | 1113Wa 0812437328 |  |  | m² | Trockenbauarbeiten | Wand | Installationswand | WI-VS |  |  | 0 | 1113HWa0812432276 |  |  |  | 0 |  |  | 0 | AllplanAttributes - W_Deckenanschluss: Gleitender Deckenanschluss Fall 01; ash_W_Trockenbau_Qualitäten: 5; Sicherheitsklasse: -
 | H2 Ebene 0 | Installationsraum | 1113Wa 0812777444 |  |  | m² | Trockenbauarbeiten | Wand | Installationswand | Installationsraum |  |  | 0 | 1113HWa0812777443 |  |  |  | 0 |  |  | 0 | AllplanAttributes - Sicherheitsklasse: -
 | H2 Ebene 0 | WI-VS | 1113Wa 0812777445 |  |  | m² | Trockenbauarbeiten | Wand | Installationswand | WI-VS |  |  | 0 | 1113HWa0812777443 |  |  |  | 0 |  |  | 0 | AllplanAttributes - W_Deckenanschluss: Gleitender Deckenanschluss Fall 01; ash_W_Trockenbau_Qualitäten: 5; Sicherheitsklasse: -
 | H2 Ebene 0 | Installationsraum | 1113Wa 0812533131 |  |  | m² | Trockenbauarbeiten | Wand | Installationswand | Installationsraum |  |  | 0 | 1113HWa0812533112 |  |  |  | 0 |  |  | 0 | AllplanAttributes - Sicherheitsklasse: -
 | H2 Ebene 0 | WI-VS | 1113Wa 0812533139 |  |  | m² | Trockenbauarbeiten | Wand | Installationswand | WI-VS |  |  | 0 | 1113HWa0812533112 |  |  |  | 0 |  |  | 0 | AllplanAttributes - W_Deckenanschluss: Gleitender Deckenanschluss Fall 01; ash_W_Trockenbau_Qualitäten: 5; Sicherheitsklasse: -
 | H2 Ebene 0 | Installationsraum | 1113Wa 0812533133 |  |  | m² | Trockenbauarbeiten | Wand | Installationswand | Installationsraum |  |  | 0 | 1113HWa0812533113 |  |  |  | 0 |  |  | 0 | AllplanAttributes - Sicherheitsklasse: -
 | H2 Ebene 0 | WI-VS | 1113Wa 0812533135 |  |  | m² | Trockenbauarbeiten | Wand | Installationswand | WI-VS |  |  | 0 | 1113HWa0812533113 |  |  |  | 0 |  |  | 0 | AllplanAttributes - W_Deckenanschluss: Gleitender Deckenanschluss Fall 01; ash_W_Trockenbau_Qualitäten: 5; Sicherheitsklasse: -
 | H2 Ebene 0 | WI-HW 60 | 1113Wa 0812500751 |  |  | m² | Zimmer- und Holzbauarbeiten | Wand | Innenwand 1-Schalig | WI-HW 60 |  |  | 0 | 1113HWa0812500638 |  |  |  | 0 |  |  | 0 | AllplanAttributes - Sicherheitsklasse: -
 | H2 Ebene 0 | WI-HW 60 | 1113Wa 0812443622 |  |  | m² | Zimmer- und Holzbauarbeiten | Wand | Innenwand 1-Schalig | WI-HW 60 |  |  | 0 | 1113HWa0812440862 |  |  |  | 0 |  |  | 0 | AllplanAttributes - Sicherheitsklasse: -
 | H2 Ebene 0 | WI-HW 60 | 1113Wa 0812443694 |  |  | m² | Zimmer- und Holzbauarbeiten | Wand | Innenwand 1-Schalig | WI-HW 60 |  |  | 0 | 1113HWa0812425834 |  |  |  | 0 |  |  | 0 | AllplanAttributes - Sicherheitsklasse: -
 | H2 Ebene 0 | WI-HW 60 | 1113Wa 0812551359 |  |  | m² | Zimmer- und Holzbauarbeiten | Wand | Innenwand 1-Schalig | WI-HW 60 |  |  | 0 | 1113HWa0812551344 |  |  |  | 0 |  |  | 0 | AllplanAttributes - Sicherheitsklasse: -
 | H2 Ebene 0 | WI-HW 60 | 1113Wa 0813576787 |  |  | m² | Zimmer- und Holzbauarbeiten | Wand | Innenwand 1-Schalig | WI-HW 60 |  |  | 0 | 1113HWa0813576786 |  |  |  | 0 | AllplanAttributes - Sicherheitsklasse: -
 | H2 Ebene 0 | WI-HW 60 | 1113Wa 0812442585 |  |  | m² | Zimmer- und Holzbauarbeiten | Wand | Innenwand 1-Schalig | WI-HW 60 |  |  | 0 | 1113HWa0812440855 |  |  |  | 0 |  |  | 0 | AllplanAttributes - Sicherheitsklasse: -
 | H2 Ebene 0 | WI-HW 60 | 1113Wa 0812437257 |  |  | m² | Zimmer- und Holzbauarbeiten | Wand | Innenwand 1-Schalig | WI-HW 60 |  |  | 0 | 1113HWa0812434402 |  |  |  | 0 |  |  | 0 | AllplanAttributes - Sicherheitsklasse: -
 | H2 Ebene 0 | WI-HW 60 | 1113Wa 0812442406 |  |  | m² | Zimmer- und Holzbauarbeiten | Wand | Innenwand 1-Schalig | WI-HW 60 |  |  | 0 | 1113HWa0812430471 |  |  |  | 0 | AllplanAttributes - Sicherheitsklasse: -
 | H2 Ebene 0 | WA-STB | 1113Wa 0812437306 |  |  | m² | Zimmer- und Holzbauarbeiten | Wand | Außenwand 1-Schalig | WA-STB |  |  | 0 | 1113HWa0812425596 |  |  |  | 0 |  |  | 0 | AllplanAttributes - Sicherheitsklasse: -
 | H2 Ebene 0 | WI-STB | 1113Wa 0812852060 |  |  | m² | Zimmer- und Holzbauarbeiten | Wand | Innenwand 1-Schalig | WI-STB |  |  | 0 | 1113HWa0812851836 |  |  |  | 0 |  |  | 0 | AllplanAttributes - Sicherheitsklasse: -
 | H2 Ebene 0 | WI-STB | 1113Wa 0812542271 | yes |  | m² | Zimmer- und Holzbauarbeiten | Wand | Außenwand 1-Schalig | WI-STB |  |  | 0 | 1113HWa0812542250 | NEW |  |  | 0 |  |  | 0 | AllplanAttributes - Ortscode_Geschoßbezeichnung: E00; Sicherheitsklasse: -
 | H2 Ebene 0 | WI-STB | 1113Wa 0812755800 | yes |  | m² | Zimmer- und Holzbauarbeiten | Wand | Außenwand 1-Schalig | WI-STB |  |  | 0 | 1113HWa0812755799 | NEW |  |  | 0 |  |  | 52 | AllplanAttributes - Sicherheitsklasse: -
 | H2 Ebene 0 | WI-LB | 1113Wa 0812841723 |  |  | m² | Trockenbauarbeiten | Wand | Außenwand 1-Schalig | WI-LB |  |  | 0 | 1113HWa0812755799 | OTHER |  |  | 0 | AllplanAttributes - ash_W_Trockenbau_Qualitäten: 9; Sicherheitsklasse: -
 | H2 Ebene 0 | WI-STB | 1113Wa 0812544542 | yes |  | m² | Zimmer- und Holzbauarbeiten | Wand | Außenwand 1-Schalig | WI-STB |  |  | 0 | 1113HWa0812544533 | NEW |  |  | 0 |  |  | 52 | AllplanAttributes - Sicherheitsklasse: -
 | H2 Ebene 0 | WI-LB | 1113Wa 0812841636 |  |  | m² | Trockenbauarbeiten | Wand | Außenwand 1-Schalig | WI-LB |  |  | 0 | 1113HWa0812544533 | OTHER |  |  | 0 | AllplanAttributes - ash_W_Trockenbau_Qualitäten: 9; Sicherheitsklasse: -
 | H2 Ebene 0 | WI-STB | 1113Wa 0812437396 | yes |  | m² | Zimmer- und Holzbauarbeiten | Wand | Außenwand 1-Schalig | WI-STB |  |  | 0 | 1113HWa0812434260 | NEW |  |  | 0 |  |  | 0 | AllplanAttributes - Ortscode_Geschoßbezeichnung: E00; Sicherheitsklasse: -
 | H2 Ebene 0 | WI-STB | 1113Wa 0812542417 | yes |  | m² | Zimmer- und Holzbauarbeiten | Wand | Außenwand 1-Schalig | WI-STB |  |  | 0 | 1113HWa0812542403 | NEW | no |  | 0 |  |  | 0 | AllplanAttributes - Ortscode_Geschoßbezeichnung: E00; Sicherheitsklasse: -
 | H2 Ebene 0 | WI-STB | 1113Wa 0812442055 | yes |  | m² | Zimmer- und Holzbauarbeiten | Wand | Außenwand 1-Schalig | WI-STB |  |  | 0 | 1113HWa0812428822 | NEW | no |  | 0 |  |  | 0 | AllplanAttributes - Ortscode_Geschoßbezeichnung: E00; Sicherheitsklasse: -
 | H2 Ebene 0 | WI-LB | 1113Wa 0813668873 |  |  | m² | Trockenbauarbeiten | Wand | Innenwand 1-Schalig | WI-LB |  |  | 0 | 1113HWa0813668869 |  |  |  | 0 |  |  | 52 | AllplanAttributes - ash_W_Trockenbau_Qualitäten: 8; Sicherheitsklasse: -
 | H2 Ebene 0 | Installationsraum | 1113Wa 0813668871 |  |  | m² | Trockenbauarbeiten | Wand | Innenwand 1-Schalig | Installationsraum |  |  | 0 | 1113HWa0813668869 |  |  |  | 0 |  |  | 52 | AllplanAttributes - Sicherheitsklasse: -
 | H2 Ebene 0 | WI-HW 60 | 1113Wa 0813668874 |  |  | m² | Zimmer- und Holzbauarbeiten | Wand | Innenwand 1-Schalig | WI-HW 60 |  |  | 0 | 1113HWa0813668869 |  |  |  | 0 |  |  | 52 | AllplanAttributes - Sicherheitsklasse: -
 | H2 Ebene 0 | WI-HW 60 | 1113Wa 0812447125 |  |  | m² | Zimmer- und Holzbauarbeiten | Wand | Innenwand 1-Schalig | WI-HW 60 |  |  | 0 | 1113HWa0812434680 |  |  |  | 0 |  |  | 52 | AllplanAttributes - Sicherheitsklasse: -
 | H2 Ebene 0 | WI-LB | 1113Wa 0812446048 |  |  | m² | Trockenbauarbeiten | Wand |  |  |  |  | 0 | 1113HWa0812425469 |  |  |  | 0 |  |  | 47 | AllplanAttributes - Ortscode_Geschoßbezeichnung: E00; W_Deckenanschluss: Gleitender Deckenanschluss Fall 03; ash_W_Trockenbau_Qualitäten: 1c; Sicherheitsklasse: -
 | H2 Ebene 0 | WI-LB | 1113Wa 0812446046 |  |  | m² | Trockenbauarbeiten | Wand |  |  |  |  | 0 | 1113HWa0812425472 |  |  |  | 0 |  |  | 47 | AllplanAttributes - Ortscode_Geschoßbezeichnung: E00; W_Deckenanschluss: Gleitender Deckenanschluss Fall 03; ash_W_Trockenbau_Qualitäten: 1c; Sicherheitsklasse: -
 | H2 Ebene 0 | WI-LB | 1113Wa 0812446044 |  |  | m² | Trockenbauarbeiten | Wand |  |  |  |  | 0 | 1113HWa0812425475 |  |  |  | 0 |  |  | 47 | AllplanAttributes - Ortscode_Geschoßbezeichnung: E00; W_Deckenanschluss: Gleitender Deckenanschluss Fall 03; ash_W_Trockenbau_Qualitäten: 1c; Sicherheitsklasse: -
 | H2 Ebene 0 | WI-LB | 1113Wa 0812439308 |  |  | m² | Trockenbauarbeiten | Wand | Innenwand 1-Schalig | WI-LB |  |  | 0 | 1113HWa0812425479 |  |  |  | 0 |  |  | 47 | AllplanAttributes - Ortscode_Geschoßbezeichnung: E00; W_Deckenanschluss: Gleitender Deckenanschluss Fall 03; ash_W_Trockenbau_Qualitäten: 1c; Sicherheitsklasse: -
 | H2 Ebene 0 | WI-LB | 1113Wa 0812438262 |  |  | m² | Trockenbauarbeiten | Wand | Innenwand 1-Schalig | WI-LB |  |  | 0 | 1113HWa0812425516 |  |  |  | 0 |  |  | 47 | AllplanAttributes - Ortscode_Geschoßbezeichnung: E00; W_Deckenanschluss: Gleitender Deckenanschluss Fall 03; ash_W_Trockenbau_Qualitäten: 1c; Sicherheitsklasse: -
 | H2 Ebene 0 | WI-LB | 1113Wa 0812438264 |  |  | m² | Trockenbauarbeiten | Wand | Innenwand 1-Schalig | WI-LB |  |  | 0 | 1113HWa0812425560 |  |  |  | 0 |  |  | 47 | AllplanAttributes - Ortscode_Geschoßbezeichnung: E00; W_Deckenanschluss: Gleitender Deckenanschluss Fall 03; ash_W_Trockenbau_Qualitäten: 1c; Sicherheitsklasse: -
 | H2 Ebene 0 | WI-LB | 1113Wa 0812438997 |  |  | m² | Trockenbauarbeiten | Wand |  |  |  |  | 0 | 1113HWa0812425571 |  |  |  | 0 |  |  | 47 | AllplanAttributes - Ortscode_Geschoßbezeichnung: E00; W_Deckenanschluss: Gleitender Deckenanschluss Fall 03; ash_W_Trockenbau_Qualitäten: 1c; Sicherheitsklasse: -
 | H2 Ebene 0 | WI-LB | 1113Wa 0812441662 |  |  | m² | Trockenbauarbeiten | Wand |  |  |  |  | 0 | 1113HWa0812440937 |  |  |  | 0 |  |  | 47 | AllplanAttributes - Ortscode_Geschoßbezeichnung: E00; W_Deckenanschluss: Gleitender Deckenanschluss Fall 03; ash_W_Trockenbau_Qualitäten: 1c; Sicherheitsklasse: -
 | H2 Ebene 0 | WI-LB | 1113Wa 0812438278 |  |  | m² | Trockenbauarbeiten | Wand | Innenwand 1-Schalig | WI-LB |  |  | 0 | 1113HWa0812435113 |  |  |  | 0 |  |  | 47 | AllplanAttributes - Ortscode_Geschoßbezeichnung: E00; W_Deckenanschluss: Gleitender Deckenanschluss Fall 03; ash_W_Trockenbau_Qualitäten: 1c; Sicherheitsklasse: -
 | H2 Ebene 0 | WI-LB | 1113Wa 0812437675 |  |  | m² | Trockenbauarbeiten | Wand |  |  |  |  | 0 | 1113HWa0812425538 |  |  |  | 0 |  |  | 47 | AllplanAttributes - Ortscode_Geschoßbezeichnung: E00; W_Deckenanschluss: Gleitender Deckenanschluss Fall 03; ash_W_Trockenbau_Qualitäten: 1c; Sicherheitsklasse: -
 | H2 Ebene 0 | WI-LB | 1113Wa 0812437673 |  |  | m² | Trockenbauarbeiten | Wand |  |  |  |  | 0 | 1113HWa0812425551 |  |  |  | 0 |  |  | 47 | AllplanAttributes - Ortscode_Geschoßbezeichnung: E00; W_Deckenanschluss: Gleitender Deckenanschluss Fall 03; ash_W_Trockenbau_Qualitäten: 1c; Sicherheitsklasse: -
 | H2 Ebene 0 | WI-LB | 1113Wa 0812437677 |  |  | m² | Trockenbauarbeiten | Wand |  |  |  |  | 0 | 1113HWa0812425533 |  |  |  | 0 |  |  | 47 | AllplanAttributes - Ortscode_Geschoßbezeichnung: E00; W_Deckenanschluss: Gleitender Deckenanschluss Fall 03; ash_W_Trockenbau_Qualitäten: 1c; Sicherheitsklasse: -
 | H2 Ebene 0 | WI-LB | 1113Wa 0812439304 |  |  | m² | Trockenbauarbeiten | Wand | Innenwand 1-Schalig | WI-LB |  |  | 0 | 1113HWa0812425510 |  |  |  | 0 |  |  | 47 | AllplanAttributes - Ortscode_Geschoßbezeichnung: E00; W_Deckenanschluss: Gleitender Deckenanschluss Fall 03; ash_W_Trockenbau_Qualitäten: 1c; Sicherheitsklasse: -
 | H2 Ebene 0 | WI-LB | 1113Wa 0812438999 |  |  | m² | Trockenbauarbeiten | Wand |  |  |  |  | 0 | 1113HWa0812425505 |  |  |  | 0 |  |  | 47 | AllplanAttributes - Ortscode_Geschoßbezeichnung: E00; W_Deckenanschluss: Gleitender Deckenanschluss Fall 03; ash_W_Trockenbau_Qualitäten: 1c; Sicherheitsklasse: -
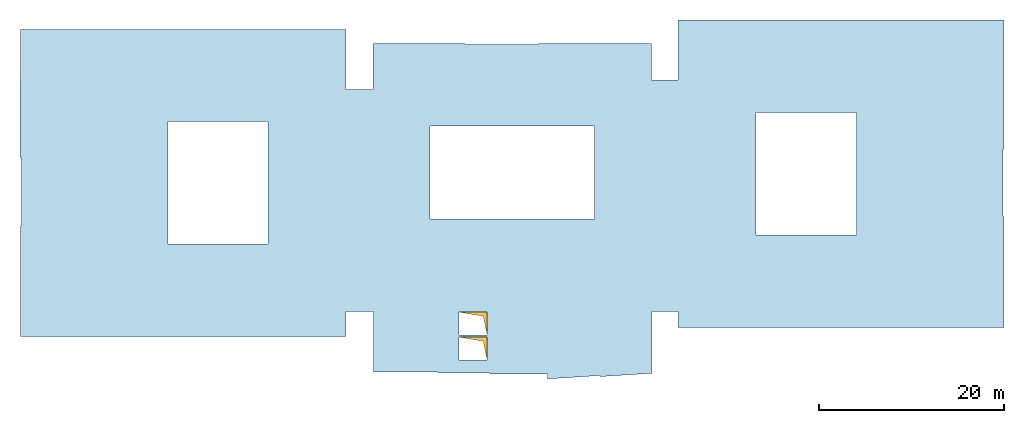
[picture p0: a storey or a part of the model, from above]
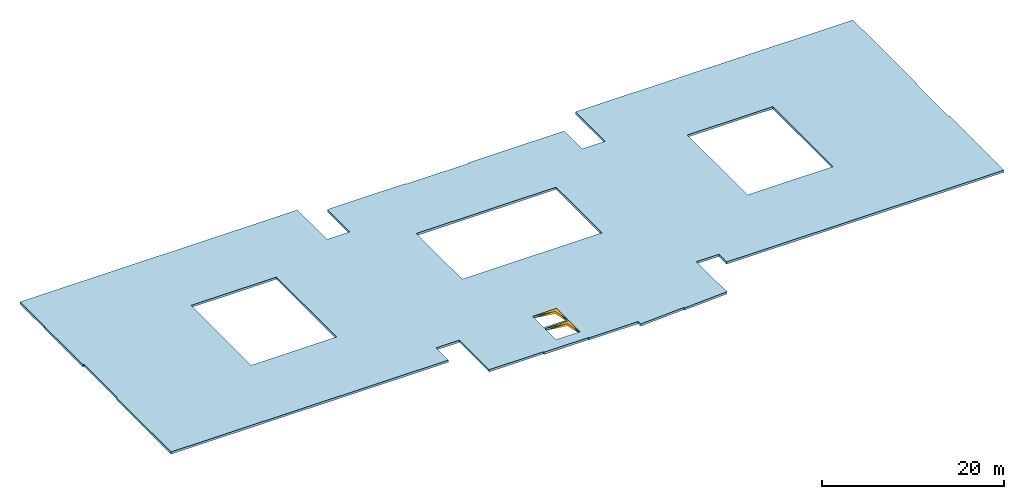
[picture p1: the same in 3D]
Properties of the parts of a building model (IFC4), part 74 of 80

# IfcWall (6826)
Name | In | Material | Allright_Bauteil_ID | 2D Interaktion | Codetext | Abrechnungsart | Gewerk | Objektname | Bezeichnung | AllplanAttributes, Material | Typ = SurfaceSpreadOfFlame | Brandschutzklasse | OKFF | P_ID | Status | LoadBearing | IsExternal | FireRating | ThermalTransmittance (W/K/m2) | Combustible | AcousticRating | Compartmentation | Reference
 | H2 Ebene 0 | WI-LB | 1113Wa 0812439306 |  |  | m² | Trockenbauarbeiten | Wand | Innenwand 1-Schalig | WI-LB |  |  | 0 | 1113HWa0812425580 |  |  |  | 0 |  |  | 47 | AllplanAttributes - Ortscode_Geschoßbezeichnung: E00; W_Deckenanschluss: Gleitender Deckenanschluss Fall 03; ash_W_Trockenbau_Qualitäten: 1c; Sicherheitsklasse: -
 | H2 Ebene 0 | WI-LB | 1113Wa 0812439001 |  |  | m² | Trockenbauarbeiten | Wand |  |  |  |  | 0 | 1113HWa0812425497 |  |  |  | 0 |  |  | 47 | AllplanAttributes - Ortscode_Geschoßbezeichnung: E00; W_Deckenanschluss: Gleitender Deckenanschluss Fall 03; ash_W_Trockenbau_Qualitäten: 1c; Sicherheitsklasse: -
 | H2 Ebene 0 | WI-LB | 1113Wa 0812446199 |  |  | m² | Trockenbauarbeiten | Wand | Innenwand 1-Schalig | WI-LB |  |  | 0 | 1113HWa0812425471 |  |  |  | 0 |  |  | 47 | AllplanAttributes - Ortscode_Geschoßbezeichnung: E00; W_Deckenanschluss: Gleitender Deckenanschluss Fall 03; ash_W_Trockenbau_Qualitäten: 1c; Sicherheitsklasse: -
 | H2 Ebene 0 | WI-LB | 1113Wa 0812446145 |  |  | m² | Trockenbauarbeiten | Wand | Innenwand 1-Schalig | WI-LB |  |  | 0 | 1113HWa0812425468 |  |  |  | 0 |  |  | 47 | AllplanAttributes - Ortscode_Geschoßbezeichnung: E00; W_Deckenanschluss: Gleitender Deckenanschluss Fall 03; ash_W_Trockenbau_Qualitäten: 1c; Sicherheitsklasse: -
 | H2 Ebene 0 | WI-HW 60 | 1113Wa 0812533137 |  |  | m² | Zimmer- und Holzbauarbeiten | Wand | Innenwand 1-Schalig | WI-HW 60 |  |  | 0 | 1113HWa0812533119 |  |  |  | 0 |  |  | 52 | AllplanAttributes - Sicherheitsklasse: -
 | H2 Ebene 0 | WI-HW 60 | 1113Wa 0812447407 |  |  | m² | Zimmer- und Holzbauarbeiten | Wand | Innenwand 1-Schalig | WI-HW 60 |  |  | 0 | 1113HWa0812435124 |  |  |  | 0 |  |  | 42 | AllplanAttributes - Sicherheitsklasse: -
 | H2 Ebene 0 | WI-LB | 1113Wa 0812443217 |  |  | m² | Trockenbauarbeiten | Wand | Innenwand 1-Schalig | WI-LB |  |  | 0 | 1113HWa0812435326 |  |  |  | 0 |  |  | 47 | AllplanAttributes - Ortscode_Geschoßbezeichnung: E00; W_Deckenanschluss: Gleitender Deckenanschluss Fall 01; ash_W_Trockenbau_Qualitäten: 1b; Sicherheitsklasse: -
 | H2 Ebene 0 | WI-LB | 1113Wa 0812444136 |  |  | m² | Trockenbauarbeiten | Wand | Innenwand 1-Schalig | WI-LB |  |  | 0 | 1113HWa0812443700 |  |  |  | 0 |  |  | 47 | AllplanAttributes - Ortscode_Geschoßbezeichnung: E00; W_Deckenanschluss: Gleitender Deckenanschluss Fall 01; ash_W_Trockenbau_Qualitäten: 1b; Sicherheitsklasse: -
 | H2 Ebene 0 | WI-LB | 1113Wa 0812444049 |  |  | m² | Trockenbauarbeiten | Wand | Innenwand 1-Schalig | WI-LB |  |  | 0 | 1113HWa0812425617 |  |  |  | 0 |  |  | 47 | AllplanAttributes - Ortscode_Geschoßbezeichnung: E00; W_Deckenanschluss: Gleitender Deckenanschluss Fall 01; ash_W_Trockenbau_Qualitäten: 1b; Sicherheitsklasse: -
 | H2 Ebene 0 | WI-LB | 1113Wa 0812438796 |  |  | m² | Trockenbauarbeiten | Wand | Innenwand 1-Schalig | WI-LB |  |  | 0 | 1113HWa0812438777 |  |  |  | 0 |  |  | 47 | AllplanAttributes - Ortscode_Geschoßbezeichnung: E00; W_Deckenanschluss: Gleitender Deckenanschluss Fall 01; ash_W_Trockenbau_Qualitäten: 1b; Sicherheitsklasse: -
 | H2 Ebene 0 | WI-LB | 1113Wa 0812437253 |  |  | m² | Trockenbauarbeiten | Wand | Innenwand 1-Schalig | WI-LB |  |  | 0 | 1113HWa0812435324 |  |  |  | 0 |  |  | 47 | AllplanAttributes - Ortscode_Geschoßbezeichnung: E00; W_Deckenanschluss: Gleitender Deckenanschluss Fall 01; ash_W_Trockenbau_Qualitäten: 1b; Sicherheitsklasse: -
 | H2 Ebene 0 | WI-LB | 1113Wa 0812437356 |  |  | m² | Trockenbauarbeiten | Wand | Innenwand 1-Schalig | WI-LB |  |  | 0 | 1113HWa0812425466 |  |  |  | 0 |  |  | 47 | AllplanAttributes - Ortscode_Geschoßbezeichnung: E00; W_Deckenanschluss: Gleitender Deckenanschluss Fall 01; ash_W_Trockenbau_Qualitäten: 1b; Sicherheitsklasse: -
 | H2 Ebene 0 | WI-LB | 1113Wa 0812437369 |  |  | m² | Trockenbauarbeiten | Wand | Innenwand 1-Schalig | WI-LB |  |  | 0 | 1113HWa0812425465 |  |  |  | 0 |  |  | 47 | AllplanAttributes - Ortscode_Geschoßbezeichnung: E00; W_Deckenanschluss: Gleitender Deckenanschluss Fall 01; ash_W_Trockenbau_Qualitäten: 1b; Sicherheitsklasse: -
 | H2 Ebene 0 | WI-LB | 1113Wa 0812441735 |  |  | m² | Trockenbauarbeiten | Wand | Innenwand 1-Schalig | WI-LB |  |  | 0 | 1113HWa0812440936 |  |  |  | 0 |  |  | 47 | AllplanAttributes - Ortscode_Geschoßbezeichnung: E00; W_Deckenanschluss: Gleitender Deckenanschluss Fall 03; ash_W_Trockenbau_Qualitäten: 1c; Sicherheitsklasse: -
 | H2 Ebene 0 | WI-LB | 1113Wa 0812442525 |  |  | m² | Trockenbauarbeiten | Wand | Innenwand 1-Schalig | WI-LB |  |  | 0 | 1113HWa0812435292 |  |  |  | 0 |  |  | 52 | AllplanAttributes - Ortscode_Geschoßbezeichnung: E00; W_Deckenanschluss: Gleitender Deckenanschluss Fall 01; ash_W_Trockenbau_Qualitäten: 1b; Sicherheitsklasse: -
 | H2 Ebene 0 | WI-LB | 1113Wa 0812438767 |  |  | m² | Trockenbauarbeiten | Wand | Innenwand 1-Schalig | WI-LB |  |  | 0 | 1113HWa0812438502 |  |  |  | 0 |  |  | 52 | AllplanAttributes - Ortscode_Geschoßbezeichnung: E00; W_Deckenanschluss: Gleitender Deckenanschluss Fall 01; ash_W_Trockenbau_Qualitäten: 1b; Sicherheitsklasse: -
 | H2 Ebene 0 | WI-HW 60 | 1113Wa 0812444104 |  |  | m² | Zimmer- und Holzbauarbeiten | Wand | Innenwand 1-Schalig | WI-HW 60 |  |  | 0 | 1113HWa0812434275 |  |  |  | 0 |  |  | 47 | AllplanAttributes - Sicherheitsklasse: -
 | H2 Ebene 0 | WI-LB | 1113Wa 0813135230 |  |  | m² | Trockenbauarbeiten | Wand | Innenwand 1-Schalig | WI-LB |  |  | 0 | 1113HWa0812434275 |  |  |  | 0 |  |  | 47 | AllplanAttributes - ash_W_Trockenbau_Qualitäten: 6; Sicherheitsklasse: -
 | H2 Ebene 0 | WI-HW 60 | 1113Wa 0812499133 |  |  | m² | Zimmer- und Holzbauarbeiten | Wand | Innenwand 1-Schalig | WI-HW 60 |  |  | 0 | 1113HWa0812499131 |  |  |  | 0 |  |  | 47 | AllplanAttributes - Sicherheitsklasse: -
 | H2 Ebene 0 | WI-LB | 1113Wa 0813136053 |  |  | m² | Trockenbauarbeiten | Wand | Innenwand 1-Schalig | WI-LB |  |  | 0 | 1113HWa0812499131 |  |  |  | 0 |  |  | 47 | AllplanAttributes - ash_W_Trockenbau_Qualitäten: 6; Sicherheitsklasse: -
 | H2 Ebene 0 | WI-HW 60 | 1113Wa 0812439595 |  |  | m² | Zimmer- und Holzbauarbeiten | Wand | Innenwand 1-Schalig | WI-HW 60 |  |  | 0 | 1113HWa0812430479 |  |  |  | 0 |  |  | 52 | AllplanAttributes - Sicherheitsklasse: -
 | H2 Ebene 0 | Installationsraum | 1113Wa 0813130358 |  |  | m² | Trockenbauarbeiten | Wand | Innenwand 1-Schalig | Installationsraum |  |  | 0 | 1113HWa0812430479 |  |  |  | 0 |  |  | 52 | AllplanAttributes - Sicherheitsklasse: -
 | H2 Ebene 0 | WI-LB | 1113Wa 0813421162 |  |  | m² | Trockenbauarbeiten | Wand | Innenwand 1-Schalig | WI-LB |  |  | 0 | 1113HWa0812430479 |  |  |  | 0 |  |  | 52 | AllplanAttributes - ash_W_Trockenbau_Qualitäten: 8; Sicherheitsklasse: -
 | H2 Ebene 0 | WI-LB | 1113Wa 0813093161 |  |  | m² | Trockenbauarbeiten | Wand | Innenwand 1-Schalig | WI-LB |  |  | 0 | 1113HWa0813093159 |  |  |  | 0 |  |  | 47 | AllplanAttributes - ash_W_Trockenbau_Qualitäten: 6; Sicherheitsklasse: -
 | H2 Ebene 0 | WI-HW 60 | 1113Wa 0813128288 |  |  | m² | Zimmer- und Holzbauarbeiten | Wand | Innenwand 1-Schalig | WI-HW 60 |  |  | 0 | 1113HWa0813093159 |  |  |  | 0 |  |  | 47 | AllplanAttributes - Sicherheitsklasse: -
 | H2 Ebene 0 | WI-LB | 1113Wa 0813420497 |  |  | m² | Trockenbauarbeiten | Wand | Innenwand 1-Schalig | WI-LB |  |  | 0 | 1113HWa0813420496 |  |  |  | 0 |  |  | 52 | AllplanAttributes - ash_W_Trockenbau_Qualitäten: 8; Sicherheitsklasse: -
 | H2 Ebene 0 | Installationsraum | 1113Wa 0813420498 |  |  | m² | Trockenbauarbeiten | Wand | Innenwand 1-Schalig | Installationsraum |  |  | 0 | 1113HWa0813420496 |  |  |  | 0 |  |  | 52 | AllplanAttributes - Sicherheitsklasse: -
 | H2 Ebene 0 | WI-HW 60 | 1113Wa 0813420499 |  |  | m² | Zimmer- und Holzbauarbeiten | Wand | Innenwand 1-Schalig | WI-HW 60 |  |  | 0 | 1113HWa0813420496 |  |  |  | 0 |  |  | 52 | AllplanAttributes - Sicherheitsklasse: -
 | H2 Ebene 0 | WI-LB | 1113Wa 0812447147 |  |  | m² | Trockenbauarbeiten | Wand | Innenwand 1-Schalig | WI-LB |  |  | 0 | 1113HWa0812430468 |  |  |  | 0 |  |  | 52 | AllplanAttributes - ash_W_Trockenbau_Qualitäten: 8; Sicherheitsklasse: -
 | H2 Ebene 0 | Installationsraum | 1113Wa 0813126806 |  |  | m² | Trockenbauarbeiten | Wand | Innenwand 1-Schalig | Installationsraum |  |  | 0 | 1113HWa0812430468 |  |  |  | 0 |  |  | 0 | AllplanAttributes - Sicherheitsklasse: -
 | H2 Ebene 0 | WI-HW 60 | 1113Wa 0813126807 |  |  | m² | Zimmer- und Holzbauarbeiten | Wand | Innenwand 1-Schalig | WI-HW 60 |  |  | 0 | 1113HWa0812430468 |  |  |  | 0 |  |  | 52 | AllplanAttributes - Sicherheitsklasse: -
 | H2 Ebene 0 | WI-LB | 1113Wa 0812447441 |  |  | m² | Trockenbauarbeiten | Wand | Innenwand 1-Schalig | WI-LB |  |  | 0 | 1113HWa0812438083 |  |  |  | 0 |  |  | 52 | AllplanAttributes - ash_W_Trockenbau_Qualitäten: 8; Sicherheitsklasse: -
 | H2 Ebene 0 | Installationsraum | 1113Wa 0813129825 |  |  | m² | Trockenbauarbeiten | Wand | Innenwand 1-Schalig | Installationsraum |  |  | 0 | 1113HWa0812438083 |  |  |  | 0 |  |  | 0 | AllplanAttributes - Sicherheitsklasse: -
 | H2 Ebene 0 | WI-HW 60 | 1113Wa 0813129826 |  |  | m² | Zimmer- und Holzbauarbeiten | Wand | Innenwand 1-Schalig | WI-HW 60 |  |  | 0 | 1113HWa0812438083 |  |  |  | 0 |  |  | 52 | AllplanAttributes - Sicherheitsklasse: -
 | H2 Ebene 0 | WI-LB | 1113Wa 0813788017 |  |  | m² | Trockenbauarbeiten | Wand | Innenwand 1-Schalig | WI-LB |  |  | 0 | 1113HWa0813788006 |  |  |  | 0 |  |  | 47 | AllplanAttributes - ash_W_Trockenbau_Qualitäten: 6; Sicherheitsklasse: -
 | H2 Ebene 0 | WI-HW 60 | 1113Wa 0813788015 |  |  | m² | Zimmer- und Holzbauarbeiten | Wand | Innenwand 1-Schalig | WI-HW 60 |  |  | 0 | 1113HWa0813788006 |  |  |  | 0 |  |  | 47 | AllplanAttributes - Sicherheitsklasse: -
 | H2 Ebene 0 | WI-LB | 1113Wa 0812492978 |  |  | m² | Trockenbauarbeiten | Wand | Innenwand 1-Schalig | WI-LB |  |  | 0 | 1113HWa0812492424 |  |  |  | 0 |  |  | 47 | AllplanAttributes - ash_W_Trockenbau_Qualitäten: 8; Sicherheitsklasse: -
 | H2 Ebene 0 | Installationsraum | 1113Wa 0813132861 |  |  | m² | Trockenbauarbeiten | Wand | Innenwand 1-Schalig | Installationsraum |  |  | 0 | 1113HWa0812492424 |  |  |  | 0 |  |  | 47 | AllplanAttributes - Sicherheitsklasse: -
 | H2 Ebene 0 | WI-HW 60 | 1113Wa 0813132862 |  |  | m² | Zimmer- und Holzbauarbeiten | Wand | Innenwand 1-Schalig | WI-HW 60 |  |  | 0 | 1113HWa0812492424 |  |  |  | 0 |  |  | 47 | AllplanAttributes - Sicherheitsklasse: -
 | H2 Ebene 0 | WI-LB | 1113Wa 0813767279 |  |  | m² | Trockenbauarbeiten | Wand | Innenwand 1-Schalig | WI-LB |  |  | 0 | 1113HWa0813767270 |  |  |  | 0 |  |  | 47 | AllplanAttributes - ash_W_Trockenbau_Qualitäten: 6; Sicherheitsklasse: -
 | H2 Ebene 0 | WI-HW 60 | 1113Wa 0813767282 |  |  | m² | Zimmer- und Holzbauarbeiten | Wand | Innenwand 1-Schalig | WI-HW 60 |  |  | 0 | 1113HWa0813767270 |  |  |  | 0 |  |  | 47 | AllplanAttributes - Sicherheitsklasse: -
 | H2 Ebene 0 | WI-LB | 1113Wa 0812439619 |  |  | m² | Trockenbauarbeiten | Wand | Innenwand 1-Schalig | WI-LB |  |  | 0 | 1113HWa0812430481 |  |  |  | 0 |  |  | 47 | AllplanAttributes - Ortscode_Geschoßbezeichnung: E00; W_Deckenanschluss: Gleitender Deckenanschluss Fall 01; ash_W_Trockenbau_Qualitäten: 1b; Sicherheitsklasse: -
 | H2 Ebene 0 | WI-LB | 1113Wa 0813070193 |  |  | m² | Trockenbauarbeiten | Wand | Innenwand 1-Schalig | WI-LB |  |  | 0 | 1113HWa0813070058 |  |  |  | 0 |  |  | 47 | AllplanAttributes - ash_W_Trockenbau_Qualitäten: 6; Sicherheitsklasse: -
 | H2 Ebene 0 | WI-HW 60 | 1113Wa 0813130141 |  |  | m² | Zimmer- und Holzbauarbeiten | Wand | Innenwand 1-Schalig | WI-HW 60 |  |  | 0 | 1113HWa0813070058 |  |  |  | 0 |  |  | 47 | AllplanAttributes - Sicherheitsklasse: -
 | H2 Ebene 0 | WI-LB | 1113Wa 0812447085 |  |  | m² | Trockenbauarbeiten | Wand | Innenwand 1-Schalig | WI-LB |  |  | 0 | 1113HWa0812435648 |  |  |  | 0 |  |  | 52 | AllplanAttributes - Ortscode_Geschoßbezeichnung: E00; W_Deckenanschluss: Gleitender Deckenanschluss Fall 01; ash_W_Trockenbau_Qualitäten: 4; Sicherheitsklasse: -
 | H2 Ebene 0 | WI-IW | 1113Wa 0812447102 |  |  | m² | Trockenbauarbeiten | Wand | Innenwand 1-Schalig | WI-IW |  |  | 0 | 1113HWa0812434684 |  |  |  | 0 |  |  | 52 | AllplanAttributes - ash_W_Trockenbau_Qualitäten: 6; Sicherheitsklasse: -
 | H2 Ebene 0 | WI-HW 60 | 1113Wa 0813140702 |  |  | m² | Zimmer- und Holzbauarbeiten | Wand | Innenwand 1-Schalig | WI-HW 60 |  |  | 0 | 1113HWa0812434684 |  |  |  | 0 |  |  | 52 | AllplanAttributes - Sicherheitsklasse: -
 | H2 Ebene 0 | WI-HW 60 | 1113Wa 0813124055 |  |  | m² | Zimmer- und Holzbauarbeiten | Wand | Innenwand 1-Schalig | WI-HW 60 |  |  | 0 | 1113HWa0813123911 |  |  |  | 0 |  |  | 47 | AllplanAttributes - Sicherheitsklasse: -
 | H2 Ebene 0 | WI-LB | 1113Wa 0813124058 |  |  | m² | Trockenbauarbeiten | Wand | Innenwand 1-Schalig | WI-LB |  |  | 0 | 1113HWa0813123911 |  |  |  | 0 |  |  | 47 | AllplanAttributes - ash_W_Trockenbau_Qualitäten: 6; Sicherheitsklasse: -
 | H2 Ebene 0 | WI-HW 60 | 1113Wa 0812443215 |  |  | m² | Zimmer- und Holzbauarbeiten | Wand | Innenwand 1-Schalig | WI-HW 60 |  |  | 0 | 1113HWa0812443023 |  |  |  | 0 |  |  | 47 | AllplanAttributes - Sicherheitsklasse: -
 | H2 Ebene 0 | WI-LB | 1113Wa 0813122147 |  |  | m² | Trockenbauarbeiten | Wand | Innenwand 1-Schalig | WI-LB |  |  | 0 | 1113HWa0812443023 |  |  |  | 0 |  |  | 47 | AllplanAttributes - ash_W_Trockenbau_Qualitäten: 6; Sicherheitsklasse: -
 | H2 Ebene 0 | WI-HW 60 | 1113Wa 0813125179 |  |  | m² | Zimmer- und Holzbauarbeiten | Wand | Innenwand 1-Schalig | WI-HW 60 |  |  | 0 | 1113HWa0813125167 |  |  |  | 0 |  |  | 47 | AllplanAttributes - Sicherheitsklasse: -
 | H2 Ebene 0 | WI-LB | 1113Wa 0813125177 |  |  | m² | Trockenbauarbeiten | Wand | Innenwand 1-Schalig | WI-LB |  |  | 0 | 1113HWa0813125167 |  |  |  | 0 |  |  | 47 | AllplanAttributes - ash_W_Trockenbau_Qualitäten: 6; Sicherheitsklasse: -
 | H2 Ebene 0 | WI-LB | 1113Wa 0813517682 |  |  | m² | Trockenbauarbeiten | Wand | Innenwand 1-Schalig | WI-LB |  |  | 0 | 1113HWa0813517477 |  |  |  | 0 |  |  | 47 | AllplanAttributes - ash_W_Trockenbau_Qualitäten: 8; Sicherheitsklasse: -
 | H2 Ebene 0 | Installationsraum | 1113Wa 0813517686 |  |  | m² | Trockenbauarbeiten | Wand | Innenwand 1-Schalig | Installationsraum |  |  | 0 | 1113HWa0813517477 |  |  |  | 0 |  |  | 47 | AllplanAttributes - Sicherheitsklasse: -
 | H2 Ebene 0 | WI-HW 60 | 1113Wa 0813517681 |  |  | m² | Zimmer- und Holzbauarbeiten | Wand | Innenwand 1-Schalig | WI-HW 60 |  |  | 0 | 1113HWa0813517477 |  |  |  | 0 |  |  | 47 | AllplanAttributes - Sicherheitsklasse: -
 | H2 Ebene 0 | WI-LB | 1113Wa 0812444061 |  |  | m² | Trockenbauarbeiten | Wand | Innenwand 1-Schalig | WI-LB |  |  | 0 | 1113HWa0812442712 |  |  |  | 0 |  |  | 47 | AllplanAttributes - ash_W_Trockenbau_Qualitäten: 8; Sicherheitsklasse: -
 | H2 Ebene 0 | Installationsraum | 1113Wa 0813118208 |  |  | m² | Trockenbauarbeiten | Wand | Innenwand 1-Schalig | Installationsraum |  |  | 0 | 1113HWa0812442712 |  |  |  | 0 |  |  | 47 | AllplanAttributes - Sicherheitsklasse: -
 | H2 Ebene 0 | WI-HW 60 | 1113Wa 0813120985 |  |  | m² | Zimmer- und Holzbauarbeiten | Wand | Innenwand 1-Schalig | WI-HW 60 |  |  | 0 | 1113HWa0812442712 |  |  |  | 0 |  |  | 47 | AllplanAttributes - Sicherheitsklasse: -
 | H2 Ebene 0 | WI-STB | 1113Wa 0812542268 | yes |  | m² | Zimmer- und Holzbauarbeiten | Wand | Außenwand 1-Schalig | WI-STB |  |  | 0 | 1113HWa0812542249 | NEW |  |  | 0 |  |  | 47 | AllplanAttributes - Ortscode_Geschoßbezeichnung: E00; Sicherheitsklasse: -
 | H2 Ebene 0 | WI-STB | 1113Wa 0812542172 | yes |  | m² | Zimmer- und Holzbauarbeiten | Wand | Außenwand 1-Schalig | WI-STB |  |  | 0 | 1113HWa0812542148 | NEW |  |  | 0 |  |  | 52 | AllplanAttributes - Ortscode_Geschoßbezeichnung: E00; Sicherheitsklasse: -
 | H2 Ebene 0 | WI-STB | 1113Wa 0812544540 | yes |  | m² | Zimmer- und Holzbauarbeiten | Wand | Außenwand 1-Schalig | WI-STB |  |  | 0 | 1113HWa0812544534 | NEW |  |  | 0 |  |  | 52 | AllplanAttributes - Ortscode_Geschoßbezeichnung: E00; Sicherheitsklasse: -
 | H2 Ebene 0 | WI-STB | 1113Wa 0812543037 | yes |  | m² | Zimmer- und Holzbauarbeiten | Wand | Außenwand 1-Schalig | WI-STB |  |  | 0 | 1113HWa0812543032 | NEW |  |  | 0 |  |  | 52 | AllplanAttributes - Sicherheitsklasse: -
 | H2 Ebene 0 | WI-STB | 1113Wa 0812543041 | yes |  | m² | Zimmer- und Holzbauarbeiten | Wand | Außenwand 1-Schalig | WI-STB |  |  | 0 | 1113HWa0812543033 | NEW |  |  | 0 |  |  | 52 | AllplanAttributes - Ortscode_Geschoßbezeichnung: E00; Sicherheitsklasse: -
 | H2 Ebene 0 | WI-STB | 1113Wa 0812447078 | yes |  | m² | Zimmer- und Holzbauarbeiten | Wand | Außenwand 1-Schalig | WI-STB |  |  | 0 | 1113HWa0812434258 | NEW |  |  | 0 |  |  | 52 | AllplanAttributes - Sicherheitsklasse: -
 | H2 Ebene 0 | WI-STB | 1113Wa 0812437398 | yes |  | m² | Zimmer- und Holzbauarbeiten | Wand | Außenwand 1-Schalig | WI-STB |  |  | 0 | 1113HWa0812429065 | NEW |  |  | 0 |  |  | 52 | AllplanAttributes - Ortscode_Geschoßbezeichnung: E00; Sicherheitsklasse: -
 | H2 Ebene 0 | WI-STB | 1113Wa 0812447121 | yes |  | m² | Zimmer- und Holzbauarbeiten | Wand | Außenwand 1-Schalig | WI-STB |  |  | 0 | 1113HWa0812438085 | NEW | no |  | 0 |  |  | 52 | AllplanAttributes - Ortscode_Geschoßbezeichnung: E00; Sicherheitsklasse: -
 | H2 Ebene 0 | WI-STB | 1113Wa 0812542413 | yes |  | m² | Zimmer- und Holzbauarbeiten | Wand | Außenwand 1-Schalig | WI-STB |  |  | 0 | 1113HWa0812542407 | NEW | no |  | 0 |  |  | 47 | AllplanAttributes - Ortscode_Geschoßbezeichnung: E00; Sicherheitsklasse: -
 | H2 Ebene 0 | WI-STB | 1113Wa 0812542416 | yes |  | m² | Zimmer- und Holzbauarbeiten | Wand | Außenwand 1-Schalig | WI-STB |  |  | 0 | 1113HWa0812542404 | NEW | no |  | 0 |  |  | 47 | AllplanAttributes - Ortscode_Geschoßbezeichnung: E00; Sicherheitsklasse: -
 | H2 Ebene 0 | WI-STB | 1113Wa 0812442083 | yes |  | m² | Zimmer- und Holzbauarbeiten | Wand | Außenwand 1-Schalig | WI-STB |  |  | 0 | 1113HWa0812430777 | NEW | no |  | 0 |  |  | 52 | AllplanAttributes - Ortscode_Geschoßbezeichnung: E00; Sicherheitsklasse: -
 | H2 Ebene 0 | WI-STB | 1113Wa 0812440543 | yes |  | m² | Zimmer- und Holzbauarbeiten | Wand | Außenwand 1-Schalig | WI-STB |  |  | 0 | 1113HWa0812430779 | NEW | no |  | 0 |  |  | 52 | AllplanAttributes - Ortscode_Geschoßbezeichnung: E00; Sicherheitsklasse: -
 | H2 Ebene 0 | WI-LB | 1113Wa 0812437386 |  |  | m² | Trockenbauarbeiten | Wand | Außenwand 1-Schalig | WI-LB |  |  | 0 | 1113HWa0812425635 |  |  |  | 0 |  |  | 0 | AllplanAttributes - Ortscode_Geschoßbezeichnung: E00; W_Deckenanschluss: Gleitender Deckenanschluss Fall 01; ash_W_Trockenbau_Qualitäten: 1b; Sicherheitsklasse: -
 | H2 Ebene 0 | WI-LB | 1113Wa 0812437302 | yes |  | m² | Trockenbauarbeiten | Wand | Innenwand 1-Schalig | WI-LB |  |  | 0 | 1113HWa0812435115 | NEW |  |  | 0 |  |  | 0 | AllplanAttributes - W_Deckenanschluss: Gleitender Deckenanschluss Fall 03; ash_W_Trockenbau_Qualitäten: 1b; Sicherheitsklasse: -
 | H2 Ebene 0 | WI-LB | 1113Wa 0812437300 | yes |  | m² | Trockenbauarbeiten | Wand | Innenwand 1-Schalig | WI-LB |  |  | 0 | 1113HWa0812425517 | NEW |  |  | 0 |  |  | 0 | AllplanAttributes - W_Deckenanschluss: Gleitender Deckenanschluss Fall 03; ash_W_Trockenbau_Qualitäten: 1b; Sicherheitsklasse: -
 | H2 Ebene 0 | WI-LB | 1113Wa 0812437719 | yes |  | m² | Trockenbauarbeiten | Wand | Innenwand 1-Schalig | WI-LB |  |  | 0 | 1113HWa0812425562 | NEW |  |  | 0 |  |  | 0 | AllplanAttributes - W_Deckenanschluss: Gleitender Deckenanschluss Fall 03; ash_W_Trockenbau_Qualitäten: 1b; Sicherheitsklasse: -
 | H2 Ebene 0 | WI-LB | 1113Wa 0813946779 | yes |  | m² | Trockenbauarbeiten | Wand | Innenwand 1-Schalig | WI-LB |  |  | 0 | 1113HWa0813946777 | NEW |  |  | 0 |  |  | 0 | AllplanAttributes - W_Deckenanschluss: Gleitender Deckenanschluss Fall 03; ash_W_Trockenbau_Qualitäten: 1b; Sicherheitsklasse: -
 | H2 Ebene 0 | WI-LB | 1113Wa 0813946783 | yes |  | m² | Trockenbauarbeiten | Wand | Innenwand 1-Schalig | WI-LB |  |  | 0 | 1113HWa0813946776 | NEW |  |  | 0 |  |  | 0 | AllplanAttributes - W_Deckenanschluss: Gleitender Deckenanschluss Fall 03; ash_W_Trockenbau_Qualitäten: 1b; Sicherheitsklasse: -
 | H2 Ebene 0 | WI-LB | 1113Wa 0812437679 | yes |  | m² | Trockenbauarbeiten | Wand | Innenwand 1-Schalig | WI-LB |  |  | 0 | 1113HWa0812425542 | NEW |  |  | 0 |  |  | 0 | AllplanAttributes - W_Deckenanschluss: Gleitender Deckenanschluss Fall 03; ash_W_Trockenbau_Qualitäten: 1b; Sicherheitsklasse: -
 | H2 Ebene 0 | WI-LB | 1113Wa 0812441627 | yes |  | m² | Trockenbauarbeiten | Wand | Innenwand 1-Schalig | WI-LB |  |  | 0 | 1113HWa0812440911 | NEW |  |  | 0 |  |  | 0 | AllplanAttributes - W_Deckenanschluss: Gleitender Deckenanschluss Fall 03; ash_W_Trockenbau_Qualitäten: 1b; Sicherheitsklasse: -
 | H2 Ebene 0 | WI-LB | 1113Wa 0812446033 | yes |  | m² | Trockenbauarbeiten | Wand | Innenwand 1-Schalig | WI-LB |  |  | 0 | 1113HWa0812445203 | NEW |  |  | 0 |  |  | 0 | AllplanAttributes - W_Deckenanschluss: Gleitender Deckenanschluss Fall 03; ash_W_Trockenbau_Qualitäten: 1b; Sicherheitsklasse: -
 | H2 Ebene 0 | WI-LB | 1113Wa 0812446106 | yes |  | m² | Trockenbauarbeiten | Wand | Innenwand 1-Schalig | WI-LB |  |  | 0 | 1113HWa0812445207 | NEW |  |  | 0 |  |  | 0 | AllplanAttributes - W_Deckenanschluss: Gleitender Deckenanschluss Fall 03; ash_W_Trockenbau_Qualitäten: 1b; Sicherheitsklasse: -
 | H2 Ebene 0 | WI-LB | 1113Wa 0812944933 | yes |  | m² | Trockenbauarbeiten | Wand | Innenwand 1-Schalig | WI-LB |  |  | 0 | 1113HWa0812944931 | NEW |  |  | 0 |  |  | 0 | AllplanAttributes - W_Deckenanschluss: Gleitender Deckenanschluss Fall 03; ash_W_Trockenbau_Qualitäten: 1b; Sicherheitsklasse: -
 | H2 Ebene 0 | WI-LB | 1113Wa 0812446102 | yes |  | m² | Trockenbauarbeiten | Wand | Innenwand 1-Schalig | WI-LB |  |  | 0 | 1113HWa0812445205 | NEW |  |  | 0 |  |  | 0 | AllplanAttributes - W_Deckenanschluss: Gleitender Deckenanschluss Fall 03; ash_W_Trockenbau_Qualitäten: 1b; Sicherheitsklasse: -
 | H2 Ebene 0 | WI-LB | 1113Wa 0812446143 | yes |  | m² | Trockenbauarbeiten | Wand | Innenwand 1-Schalig | WI-LB |  |  | 0 | 1113HWa0812445234 | NEW |  |  | 0 |  |  | 0 | AllplanAttributes - W_Deckenanschluss: Gleitender Deckenanschluss Fall 03; ash_W_Trockenbau_Qualitäten: 1b; Sicherheitsklasse: -
 | H2 Ebene 0 | WI-LB | 1113Wa 0812446714 | yes |  | m² | Trockenbauarbeiten | Wand | Innenwand 1-Schalig | WI-LB |  |  | 0 | 1113HWa0812446711 | NEW |  |  | 0 |  |  | 0 | AllplanAttributes - W_Deckenanschluss: Gleitender Deckenanschluss Fall 03; ash_W_Trockenbau_Qualitäten: 1b; Sicherheitsklasse: -
 | H2 Ebene 0 | WI-HW 60 | 1113Wa 0813975951 | yes |  | m² | Zimmer- und Holzbauarbeiten | Wand | Innenwand 1-Schalig | WI-HW 60 |  |  | 0 | 1113HWa0813975950 | NEW |  |  | 0 | AllplanAttributes - Sicherheitsklasse: -
 | H2 Ebene 0 | WI-LW 60 | 1113Wa 0813987295 | yes |  | m² | Trockenbauarbeiten | Wand | Innenwand 1-Schalig | WI-LW 60 |  |  | 0 | 1113HWa0813987294 | NEW |  |  | 0 | AllplanAttributes - W_Deckenanschluss: Gleitender Deckenanschluss Fall 01; Sicherheitsklasse: -
 | H2 Ebene 0 | WI-LW 60 | 1113Wa 0813987307 | yes |  | m² | Trockenbauarbeiten | Wand | Innenwand 1-Schalig | WI-LW 60 |  |  | 0 | 1113HWa0813987306 | NEW |  |  | 0 | AllplanAttributes - W_Deckenanschluss: Gleitender Deckenanschluss Fall 01; Sicherheitsklasse: -
 | H2 Ebene 0 | WI-LW 60 | 1113Wa 0813987321 | yes |  | m² | Trockenbauarbeiten | Wand | Innenwand 1-Schalig | WI-LW 60 |  |  | 0 | 1113HWa0813987320 | NEW |  |  | 0 | AllplanAttributes - W_Deckenanschluss: Gleitender Deckenanschluss Fall 01; Sicherheitsklasse: -
 | H2 Ebene 0 | WI-LW 60 | 1113Wa 0813987288 | yes |  | m² | Trockenbauarbeiten | Wand | Innenwand 1-Schalig | WI-LW 60 |  |  | 0 | 1113HWa0813987287 | NEW |  |  | 0 | AllplanAttributes - W_Deckenanschluss: Gleitender Deckenanschluss Fall 01; Sicherheitsklasse: -
 | H2 Ebene 0 | WI-HW 60 | 1113Wa 0812551373 |  |  | m² | Zimmer- und Holzbauarbeiten | Wand | Innenwand 1-Schalig | WI-HW 60 |  |  | 0 | 1113HWa0812551364 |  |  |  | 0 |  |  | 0 | AllplanAttributes - Sicherheitsklasse: -
 | H2 Ebene 0 | WI-HW 60 | 1113Wa 0813987239 | yes |  | m² | Zimmer- und Holzbauarbeiten | Wand | Innenwand 1-Schalig | WI-HW 60 |  |  | 0 | 1113HWa0813987238 | NEW |  |  | 0 | AllplanAttributes - Sicherheitsklasse: -
 | H2 Ebene 0 | WI-HW 60 | 1113Wa 0813987244 | yes |  | m² | Zimmer- und Holzbauarbeiten | Wand | Innenwand 1-Schalig | WI-HW 60 |  |  | 0 | 1113HWa0813987243 | NEW |  |  | 0 | AllplanAttributes - Sicherheitsklasse: -
 | H2 Ebene 0 | WI-HW 60 | 1113Wa 0813987256 | yes |  | m² | Zimmer- und Holzbauarbeiten | Wand | Innenwand 1-Schalig | WI-HW 60 |  |  | 0 | 1113HWa0813987255 | NEW |  |  | 0 | AllplanAttributes - Sicherheitsklasse: -
 | H2 Ebene 0 | WI-HW 60 | 1113Wa 0813987270 | yes |  | m² | Zimmer- und Holzbauarbeiten | Wand | Innenwand 1-Schalig | WI-HW 60 |  |  | 0 | 1113HWa0813987269 | NEW |  |  | 0 | AllplanAttributes - Sicherheitsklasse: -
 | H2 Ebene 0 | WI-LB | 1113Wa 0812437922 | yes |  | m² | Trockenbauarbeiten | Wand | Innenwand 1-Schalig | WI-LB |  |  | 0 | 1113HWa0812434542 |  |  |  | 0 | AllplanAttributes - Ortscode_Geschoßbezeichnung: E00; W_Deckenanschluss: Gleitender Deckenanschluss Fall 01; ash_W_Trockenbau_Qualitäten: 4; Sicherheitsklasse: -
 | H2 Ebene 0 | WI-LB | 1113Wa 0812439312 |  |  | m² | Trockenbauarbeiten | Wand |  |  |  |  | 0 | 1113HWa0812425499 |  |  |  | 0 |  |  | 0 | AllplanAttributes - Ortscode_Geschoßbezeichnung: E00; W_Deckenanschluss: Gleitender Deckenanschluss Fall 03; ash_W_Trockenbau_Qualitäten: 10a; Sicherheitsklasse: -
 | H2 Ebene 0 | WI-LB | 1113Wa 0812439344 |  |  | m² | Trockenbauarbeiten | Wand |  |  |  |  | 0 | 1113HWa0812425564 |  |  |  | 0 |  |  | 0 | AllplanAttributes - Ortscode_Geschoßbezeichnung: E00; W_Deckenanschluss: Gleitender Deckenanschluss Fall 03; ash_W_Trockenbau_Qualitäten: 10a; Sicherheitsklasse: -
 | H2 Ebene 0 | WI-LB | 1113Wa 0812439340 |  |  | m² | Trockenbauarbeiten | Wand |  |  |  |  | 0 | 1113HWa0812425573 |  |  |  | 0 |  |  | 0 | AllplanAttributes - Ortscode_Geschoßbezeichnung: E00; W_Deckenanschluss: Gleitender Deckenanschluss Fall 03; ash_W_Trockenbau_Qualitäten: 10a; Sicherheitsklasse: -
 | H2 Ebene 0 | WI-LB | 1113Wa 0812439316 |  |  | m² | Trockenbauarbeiten | Wand |  |  |  |  | 0 | 1113HWa0812427802 |  |  |  | 0 |  |  | 0 | AllplanAttributes - Ortscode_Geschoßbezeichnung: E00; W_Deckenanschluss: Gleitender Deckenanschluss Fall 03; ash_W_Trockenbau_Qualitäten: 10a; Sicherheitsklasse: -
 | H2 Ebene 0 | WI-LB | 1113Wa 0812437755 |  |  | m² | Trockenbauarbeiten | Wand |  |  |  |  | 0 | 1113HWa0812425507 |  |  |  | 0 |  |  | 0 | AllplanAttributes - Ortscode_Geschoßbezeichnung: E00; W_Deckenanschluss: Gleitender Deckenanschluss Fall 03; ash_W_Trockenbau_Qualitäten: 10a; Sicherheitsklasse: -
 | H2 Ebene 0 | WI-LB | 1113Wa 0812437729 |  |  | m² | Trockenbauarbeiten | Wand |  |  |  |  | 0 | 1113HWa0812425574 |  |  |  | 0 |  |  | 0 | AllplanAttributes - Ortscode_Geschoßbezeichnung: E00; W_Deckenanschluss: Gleitender Deckenanschluss Fall 03; ash_W_Trockenbau_Qualitäten: 10a; Sicherheitsklasse: -
 | H2 Ebene 0 | WI-LB | 1113Wa 0812437681 | yes |  | m² | Trockenbauarbeiten | Wand | Innenwand 1-Schalig | WI-LB |  |  | 0 | 1113HWa0812425512 | NEW |  |  | 0 |  |  | 0 | AllplanAttributes - W_Deckenanschluss: Gleitender Deckenanschluss Fall 03; ash_W_Trockenbau_Qualitäten: 1b; Sicherheitsklasse: -
 | H2 Ebene 0 | WI-LB | 1113Wa 0812944913 | yes |  | m² | Trockenbauarbeiten | Wand | Innenwand 1-Schalig | WI-LB |  |  | 0 | 1113HWa0812944912 | NEW |  |  | 0 |  |  | 0 | AllplanAttributes - W_Deckenanschluss: Gleitender Deckenanschluss Fall 03; ash_W_Trockenbau_Qualitäten: 1b; Sicherheitsklasse: -
 | H2 Ebene 0 | WI-LB | 1113Wa 0812437727 | yes |  | m² | Trockenbauarbeiten | Wand | Innenwand 1-Schalig | WI-LB |  |  | 0 | 1113HWa0812425582 | NEW |  |  | 0 |  |  | 0 | AllplanAttributes - W_Deckenanschluss: Gleitender Deckenanschluss Fall 03; ash_W_Trockenbau_Qualitäten: 1b; Sicherheitsklasse: -
 | H2 Ebene 0 | WI-LB | 1113Wa 0812437725 | yes |  | m² | Trockenbauarbeiten | Wand | Innenwand 1-Schalig | WI-LB |  |  | 0 | 1113HWa0812425481 | NEW |  |  | 0 |  |  | 0 | AllplanAttributes - W_Deckenanschluss: Gleitender Deckenanschluss Fall 03; ash_W_Trockenbau_Qualitäten: 1b; Sicherheitsklasse: -
 | H2 Ebene 0 | WI-LB | 1113Wa 0813946781 | yes |  | m² | Trockenbauarbeiten | Wand | Innenwand 1-Schalig | WI-LB |  |  | 0 | 1113HWa0813946775 | NEW |  |  | 0 |  |  | 0 | AllplanAttributes - W_Deckenanschluss: Gleitender Deckenanschluss Fall 03; ash_W_Trockenbau_Qualitäten: 1b; Sicherheitsklasse: -
 | H2 Ebene 0 | WI-LB | 1113Wa 0814015503 |  |  | m² | Trockenbauarbeiten | Wand | Innenwand 1-Schalig | WI-LB |  |  | 0 | 1113HWa0814015502 | OTHER |  |  | 0 |  |  | 47 | AllplanAttributes - ash_W_Trockenbau_Qualitäten: 8; Sicherheitsklasse: -
 | H2 Ebene 0 | Installationsraum | 1113Wa 0814015504 | yes |  | m² | Trockenbauarbeiten | Wand | Innenwand 1-Schalig | Installationsraum |  |  | 0 | 1113HWa0814015502 | NEW |  |  | 0 |  |  | 47 | AllplanAttributes - Sicherheitsklasse: -
 | H2 Ebene 0 | WI-HW 60 | 1113Wa 0814015505 | yes |  | m² | Zimmer- und Holzbauarbeiten | Wand | Innenwand 1-Schalig | WI-HW 60 |  |  | 0 | 1113HWa0814015502 | NEW |  |  | 0 |  |  | 47 | AllplanAttributes - Sicherheitsklasse: -
 | H2 Ebene 0 | WI-HW 60 | 1113Wa 0814015517 | yes |  | m² | Zimmer- und Holzbauarbeiten | Wand | Innenwand 1-Schalig | WI-HW 60 |  |  | 0 | 1113HWa0814015516 | NEW |  |  | 0 |  |  | 47 | AllplanAttributes - Sicherheitsklasse: -
 | H2 Ebene 0 | WI-LB | 1113Wa 0814019528 |  |  | m² | Trockenbauarbeiten | Wand | Innenwand 1-Schalig | WI-LB |  |  | 0 | 1113HWa0814019526 |  |  |  | 0 |  |  | 0 | AllplanAttributes - Ortscode_Geschoßbezeichnung: E00; W_Deckenanschluss: Gleitender Deckenanschluss Fall 01; ash_W_Trockenbau_Qualitäten: 1b; Sicherheitsklasse: -
 | H2 Ebene 0 | WI-LB | 1113Wa 0814026847 | yes |  | m² | Trockenbauarbeiten | Wand | Innenwand 1-Schalig | WI-LB |  |  | 0 | 1113HWa0814026846 |  |  |  | 0 |  |  | 0 | AllplanAttributes - W_Deckenanschluss: Gleitender Deckenanschluss Fall 01; ash_W_Trockenbau_Qualitäten: 1b; Sicherheitsklasse: -
 | H2 Ebene 0 | WI-LB | 1113Wa 0814027217 | yes |  | m² | Trockenbauarbeiten | Wand | Innenwand 1-Schalig | WI-LB |  |  | 0 | 1113HWa0814027216 | NEW |  |  | 0 |  |  | 47 | AllplanAttributes - W_Deckenanschluss: Gleitender Deckenanschluss Fall 01; ash_W_Trockenbau_Qualitäten: 1b; Sicherheitsklasse: -
 | H2 Ebene 0 | WI-LB | 1113Wa 0814027222 | yes |  | m² | Trockenbauarbeiten | Wand | Innenwand 1-Schalig | WI-LB |  |  | 0 | 1113HWa0814027221 | NEW |  |  | 0 |  |  | 47 | AllplanAttributes - W_Deckenanschluss: Gleitender Deckenanschluss Fall 01; ash_W_Trockenbau_Qualitäten: 1a; Sicherheitsklasse: -
 | H2 Ebene 0 | WI-LB | 1113Wa 0814027515 | yes | Codetext | m² | Trockenbauarbeiten | Wand | Innenwand 1-Schalig | WI-LB | 0 | A | 3.75 | 1113HWa0814027514 | NEW | no | no | 0 | 0 | no | 0 | no | Codetext | AllplanAttributes - W_Deckenanschluss: Gleitender Deckenanschluss Fall 01; Positionsnummer_Text: U100
 | H2 Ebene 0 | WI-LB | 1113Wa 0814028234 | yes |  | m² | Trockenbauarbeiten | Wand | Innenwand 1-Schalig | WI-LB |  |  | 0 | 1113HWa0814028232 | NEW |  |  | 0 |  |  | 0 | AllplanAttributes - W_Deckenanschluss: Gleitender Deckenanschluss Fall 01; ash_W_Trockenbau_Qualitäten: 1a; Sicherheitsklasse: -
 | H2 Ebene 0 | WI-LB | 1113Wa 0812443007 | yes |  | m² | Trockenbauarbeiten | Wand | Innenwand 1-Schalig | WI-LB |  |  | 0 | 1113HWa0812442703 | NEW |  |  | 0 |  |  | 0 | AllplanAttributes - W_Deckenanschluss: Gleitender Deckenanschluss Fall 01; ash_W_Trockenbau_Qualitäten: 1b; Sicherheitsklasse: -
 | H2 Ebene 0 | WI-LB | 1113Wa 0814028509 | yes |  | m² | Trockenbauarbeiten | Wand | Innenwand 1-Schalig | WI-LB |  |  | 0 | 1113HWa0814028507 | NEW |  |  | 0 |  |  | 0 | AllplanAttributes - W_Deckenanschluss: Gleitender Deckenanschluss Fall 01; ash_W_Trockenbau_Qualitäten: 1a; Sicherheitsklasse: -
 | H2 Ebene 0 | WI-LB | 1113Wa 0814028609 | yes |  | m² | Trockenbauarbeiten | Wand | Innenwand 1-Schalig | WI-LB |  |  | 0 | 1113HWa0814028608 | NEW |  |  | 0 |  |  | 0 | AllplanAttributes - W_Deckenanschluss: Gleitender Deckenanschluss Fall 01; ash_W_Trockenbau_Qualitäten: 1b; Sicherheitsklasse: -
 | H2 Ebene 0 | WI-LB | 1113Wa 0812437379 |  |  | m² | Trockenbauarbeiten | Wand | Innenwand 1-Schalig | WI-LB |  |  | 0 | 1113HWa0812428611 |  |  |  | 0 |  |  | 0 | AllplanAttributes - Ortscode_Geschoßbezeichnung: E00; W_Deckenanschluss: Gleitender Deckenanschluss Fall 01; ash_W_Trockenbau_Qualitäten: 1b; Sicherheitsklasse: -
 | H2 Ebene 0 | WI-LB | 1113Wa 0814028654 | yes |  | m² | Trockenbauarbeiten | Wand | Innenwand 1-Schalig | WI-LB |  |  | 0 | 1113HWa0814028652 | NEW |  |  | 0 |  |  | 0 | AllplanAttributes - W_Deckenanschluss: Gleitender Deckenanschluss Fall 01; ash_W_Trockenbau_Qualitäten: 1b; Sicherheitsklasse: -
 | H2 Ebene 0 | WI-LB | 1113Wa 0812437374 | yes |  | m² | Trockenbauarbeiten | Wand | Innenwand 1-Schalig | WI-LB |  |  | 0 | 1113HWa0812430876 | NEW |  |  | 0 |  |  | 0 | AllplanAttributes - W_Deckenanschluss: Gleitender Deckenanschluss Fall 01; ash_W_Trockenbau_Qualitäten: 1a; Sicherheitsklasse: -
 | H2 Ebene 0 | WI-HW 60 | 1113Wa 0812447127 | yes |  | m² | Zimmer- und Holzbauarbeiten | Wand | Innenwand 1-Schalig | WI-HW 60 |  |  | 0 | 1113HWa0812430569 | NEW |  |  | 0 |  |  | 52 | AllplanAttributes - Sicherheitsklasse: -
 | H2 Ebene 0 | WI-LB | 1113Wa 0813128449 |  |  | m² | Trockenbauarbeiten | Wand | Innenwand 1-Schalig | WI-LB |  |  | 0 | 1113HWa0812430569 | OTHER |  |  | 0 |  |  | 47 | AllplanAttributes - ash_W_Trockenbau_Qualitäten: 6; Sicherheitsklasse: -
 | H2 Ebene 0 | WI-LB | 1113Wa 0813516874 |  |  | m² | Trockenbauarbeiten | Wand | Innenwand 1-Schalig | WI-LB |  |  | 0 | 1113HWa0813516500 | OTHER |  |  | 0 |  |  | 47 | AllplanAttributes - ash_W_Trockenbau_Qualitäten: 8; Sicherheitsklasse: -
 | H2 Ebene 0 | Installationsraum | 1113Wa 0813516873 | yes |  | m² | Trockenbauarbeiten | Wand | Innenwand 1-Schalig | Installationsraum |  |  | 0 | 1113HWa0813516500 | NEW |  |  | 0 |  |  | 47 | AllplanAttributes - Sicherheitsklasse: -
 | H2 Ebene 0 | WI-HW 60 | 1113Wa 0813516876 | yes |  | m² | Zimmer- und Holzbauarbeiten | Wand | Innenwand 1-Schalig | WI-HW 60 |  |  | 0 | 1113HWa0813516500 | NEW |  |  | 0 |  |  | 47 | AllplanAttributes - Sicherheitsklasse: -
 | H2 Ebene 0 | WI-LB | 1113Wa 0813151139 |  |  | m² | Trockenbauarbeiten | Wand | Innenwand 1-Schalig | WI-LB |  |  | 0 | 1113HWa0813151138 |  |  |  |  |  |  | 0 | AllplanAttributes - W_Deckenanschluss: Gleitender Deckenanschluss Fall 01; ash_W_Trockenbau_Qualitäten: 18
 | H2 Ebene 0 | WI-LB | 1113Wa 0813151218 |  |  | m² | Trockenbauarbeiten | Wand | Innenwand 1-Schalig | WI-LB |  |  | 0 | 1113HWa0813151216 |  |  |  |  |  |  | 0 | AllplanAttributes - W_Deckenanschluss: Gleitender Deckenanschluss Fall 01; ash_W_Trockenbau_Qualitäten: 18
 | H2 Ebene 0 | WI-LB | 1113Wa 0814113552 | yes |  | m² | Trockenbauarbeiten | Wand | Innenwand 1-Schalig | WI-LB |  |  | 0 | 1113HWa0814113551 | NEW | no |  |  |  |  | 47 | AllplanAttributes - W_Deckenanschluss: Gleitender Deckenanschluss Fall 01; ash_W_Trockenbau_Qualitäten: 8
 | H2 Ebene 0 | WI-LB | 1113Wa 0814114171 | yes |  | m² | Trockenbauarbeiten | Wand | Innenwand 1-Schalig | WI-LB |  |  | 0 | 1113HWa0814114170 | NEW | no |  |  |  |  | 47 | AllplanAttributes - W_Deckenanschluss: Gleitender Deckenanschluss Fall 01; ash_W_Trockenbau_Qualitäten: 8
 | H2 Ebene 0 | WI-HW 60 | 1113Wa 0814115959 | yes |  | m² | Zimmer- und Holzbauarbeiten | Wand | Innenwand 1-Schalig | WI-HW 60 |  |  | 0 | 1113HWa0814115952 |  |  |  | 0 |  |  | 47 | AllplanAttributes - Sicherheitsklasse: -
 | H2 Ebene 0 | WI-LB | 1113Wa 0814115963 |  |  | m² | Trockenbauarbeiten | Wand | Innenwand 1-Schalig | WI-LB |  |  | 0 | 1113HWa0814115952 |  |  |  | 0 |  |  | 47 | AllplanAttributes - ash_W_Trockenbau_Qualitäten: 6; Sicherheitsklasse: -
 | H2 Ebene 0 | WI-HW 60 | 1113Wa 0814117466 | yes |  | m² | Zimmer- und Holzbauarbeiten | Wand | Innenwand 1-Schalig | WI-HW 60 |  |  | 0 | 1113HWa0814117409 | NEW |  |  | 0 |  |  | 47 | AllplanAttributes - Sicherheitsklasse: -
 | H2 Ebene 0 | WI-HW 60 | 1113Wa 0814120207 | yes |  | m² | Zimmer- und Holzbauarbeiten | Wand | Innenwand 1-Schalig | WI-HW 60 |  |  | 0 | 1113HWa0814120164 | NEW |  |  | 0 |  |  | 47 | AllplanAttributes - Sicherheitsklasse: -
 | H2 Ebene 0 | WI-HW 60 | 1113Wa 0814121386 | yes |  | m² | Zimmer- und Holzbauarbeiten | Wand | Innenwand 1-Schalig | WI-HW 60 |  |  | 0 | 1113HWa0814121342 |  |  |  | 0 |  |  | 47 | AllplanAttributes - Sicherheitsklasse: -
 | H2 Ebene 0 | WI-LB | 1113Wa 0814121391 |  |  | m² | Trockenbauarbeiten | Wand | Innenwand 1-Schalig | WI-LB |  |  | 0 | 1113HWa0814121342 |  |  |  | 0 |  |  | 47 | AllplanAttributes - ash_W_Trockenbau_Qualitäten: 6; Sicherheitsklasse: -
 | H2 Ebene 0 | WI-HW 60 | 1113Wa 0814121993 | yes |  | m² | Zimmer- und Holzbauarbeiten | Wand | Innenwand 1-Schalig | WI-HW 60 |  |  | 0 | 1113HWa0814121975 | NEW |  |  | 0 |  |  | 47 | AllplanAttributes - Sicherheitsklasse: -
 | H2 Ebene 0 | WI-LB | 1113Wa 0812441634 |  |  | m² | Trockenbauarbeiten | Wand |  |  |  |  | 0 | 1113HWa0812440914 |  |  |  | 0 |  |  | 0 | AllplanAttributes - Ortscode_Geschoßbezeichnung: E00; W_Deckenanschluss: Gleitender Deckenanschluss Fall 03; ash_W_Trockenbau_Qualitäten: 10a; Sicherheitsklasse: -
 | H2 Ebene 0 | WI-LB | 1113Wa 0812441697 |  |  | m² | Trockenbauarbeiten | Wand |  |  |  |  | 0 | 1113HWa0812440915 |  |  |  | 0 |  |  | 0 | AllplanAttributes - Ortscode_Geschoßbezeichnung: E00; W_Deckenanschluss: Gleitender Deckenanschluss Fall 03; ash_W_Trockenbau_Qualitäten: 10a; Sicherheitsklasse: -
 | H2 Ebene 0 | WI-HW 60 | 1113Wa 0814123757 |  |  | m² | Zimmer- und Holzbauarbeiten | Wand | Innenwand 1-Schalig | WI-HW 60 |  |  | 0 | 1113HWa0814123126 |  |  |  | 0 |  |  | 47 | AllplanAttributes - Sicherheitsklasse: -
 | H2 Ebene 0 | WI-HW 60 | 1113Wa 0812446773 | yes |  | m² | Zimmer- und Holzbauarbeiten | Wand | Innenwand 1-Schalig | WI-HW 60 |  |  | 0 | 1113HWa0812444214 | NEW |  |  | 0 |  |  | 47 | AllplanAttributes - Sicherheitsklasse: -
 | H2 Ebene 0 | WI-LB | 1113Wa 0814126098 |  |  | m² | Trockenbauarbeiten | Wand | Innenwand 1-Schalig | WI-LB |  |  | 0 | 1113HWa0812444214 | OTHER |  |  | 0 |  |  | 47 | AllplanAttributes - ash_W_Trockenbau_Qualitäten: 6; Sicherheitsklasse: -
 | H2 Ebene 0 | WI-LB | 1113Wa 0812446171 |  |  | m² | Trockenbauarbeiten | Wand |  |  |  |  | 0 | 1113HWa0812445210 |  |  |  | 0 |  |  | 0 | AllplanAttributes - Ortscode_Geschoßbezeichnung: E00; W_Deckenanschluss: Gleitender Deckenanschluss Fall 03; ash_W_Trockenbau_Qualitäten: 10a; Sicherheitsklasse: -
 | H2 Ebene 0 | WI-LB | 1113Wa 0812446187 |  |  | m² | Trockenbauarbeiten | Wand |  |  |  |  | 0 | 1113HWa0812445211 |  |  |  | 0 |  |  | 0 | AllplanAttributes - Ortscode_Geschoßbezeichnung: E00; W_Deckenanschluss: Gleitender Deckenanschluss Fall 03; ash_W_Trockenbau_Qualitäten: 10a; Sicherheitsklasse: -
 | H2 Ebene 0 | WI-HW 60 | 1113Wa 0814125182 |  |  | m² | Zimmer- und Holzbauarbeiten | Wand | Innenwand 1-Schalig | WI-HW 60 |  |  | 0 | 1113HWa0814124661 |  |  |  | 0 |  |  | 47 | AllplanAttributes - Sicherheitsklasse: -
 | H2 Ebene 0 | WI-LB | 1113Wa 0814125184 |  |  | m² | Trockenbauarbeiten | Wand | Innenwand 1-Schalig | WI-LB |  |  | 0 | 1113HWa0814124661 |  |  |  | 0 |  |  | 47 | AllplanAttributes - ash_W_Trockenbau_Qualitäten: 6; Sicherheitsklasse: -
 | H2 Ebene 0 | WI-HW 60 | 1113Wa 0814127481 | yes |  | m² | Zimmer- und Holzbauarbeiten | Wand | Innenwand 1-Schalig | WI-HW 60 |  |  | 0 | 1113HWa0814126885 | NEW |  |  | 0 |  |  | 47 | AllplanAttributes - Sicherheitsklasse: -
 | H2 Ebene 0 | WI-LB | 1113Wa 0812446175 |  |  | m² | Trockenbauarbeiten | Wand |  |  |  |  | 0 | 1113HWa0812445222 |  |  |  | 0 |  |  | 0 | AllplanAttributes - Ortscode_Geschoßbezeichnung: E00; W_Deckenanschluss: Gleitender Deckenanschluss Fall 03; ash_W_Trockenbau_Qualitäten: 10a; Sicherheitsklasse: -
 | H2 Ebene 0 | WI-LB | 1113Wa 0812446183 |  |  | m² | Trockenbauarbeiten | Wand |  |  |  |  | 0 | 1113HWa0812445224 |  |  |  | 0 |  |  | 0 | AllplanAttributes - Ortscode_Geschoßbezeichnung: E00; W_Deckenanschluss: Gleitender Deckenanschluss Fall 03; ash_W_Trockenbau_Qualitäten: 10a; Sicherheitsklasse: -
 | H2 Ebene 0 | WI-HW 60 | 1113Wa 0814128496 |  |  | m² | Zimmer- und Holzbauarbeiten | Wand | Innenwand 1-Schalig | WI-HW 60 |  |  | 0 | 1113HWa0814128106 |  |  |  | 0 |  |  | 47 | AllplanAttributes - Sicherheitsklasse: -
 | H2 Ebene 0 | WI-LB | 1113Wa 0814128494 |  |  | m² | Trockenbauarbeiten | Wand | Innenwand 1-Schalig | WI-LB |  |  | 0 | 1113HWa0814128106 |  |  |  | 0 |  |  | 47 | AllplanAttributes - ash_W_Trockenbau_Qualitäten: 6; Sicherheitsklasse: -
 | H2 Ebene 0 | WI-HW 60 | 1113Wa 0814129525 | yes |  | m² | Zimmer- und Holzbauarbeiten | Wand | Innenwand 1-Schalig | WI-HW 60 |  |  | 0 | 1113HWa0814129197 | NEW |  |  | 0 |  |  | 47 | AllplanAttributes - Sicherheitsklasse: -
 | H2 Ebene 0 | WI-LB | 1113Wa 0812446179 |  |  | m² | Trockenbauarbeiten | Wand |  |  |  |  | 0 | 1113HWa0812445237 |  |  |  | 0 |  |  | 0 | AllplanAttributes - Ortscode_Geschoßbezeichnung: E00; W_Deckenanschluss: Gleitender Deckenanschluss Fall 03; ash_W_Trockenbau_Qualitäten: 10a; Sicherheitsklasse: -
 | H2 Ebene 0 | WI-LB | 1113Wa 0812446167 |  |  | m² | Trockenbauarbeiten | Wand |  |  |  |  | 0 | 1113HWa0812445238 |  |  |  | 0 |  |  | 0 | AllplanAttributes - Ortscode_Geschoßbezeichnung: E00; W_Deckenanschluss: Gleitender Deckenanschluss Fall 03; ash_W_Trockenbau_Qualitäten: 10a; Sicherheitsklasse: -
 | H2 Ebene 0 | WI-HW 60 | 1113Wa 0814130376 | yes |  | m² | Zimmer- und Holzbauarbeiten | Wand | Innenwand 1-Schalig | WI-HW 60 |  |  | 0 | 1113HWa0814130369 | NEW |  |  | 0 |  |  | 47 | AllplanAttributes - Sicherheitsklasse: -
 | H2 Ebene 0 | WI-LB | 1113Wa 0812446743 |  |  | m² | Trockenbauarbeiten | Wand |  |  |  |  | 0 | 1113HWa0812445891 |  |  |  | 0 |  |  | 0 | AllplanAttributes - Ortscode_Geschoßbezeichnung: E00; W_Deckenanschluss: Gleitender Deckenanschluss Fall 03; ash_W_Trockenbau_Qualitäten: 10a; Sicherheitsklasse: -
 | H2 Ebene 0 | WI-HW 60 | 1113Wa 0812438230 | yes |  | m² | Zimmer- und Holzbauarbeiten | Wand | Innenwand 1-Schalig | WI-HW 60 |  |  | 0 | 1113HWa0812438184 | NEW |  |  | 0 |  |  | 47 | AllplanAttributes - Sicherheitsklasse: -
 | H2 Ebene 0 | WI-LB | 1113Wa 0812439886 |  |  | m² | Trockenbauarbeiten | Wand | Innenwand 1-Schalig | WI-LB |  |  | 0 | 1113HWa0812438082 |  |  |  | 0 |  |  | 47 | AllplanAttributes - ash_W_Trockenbau_Qualitäten: 6; Sicherheitsklasse: -
 | H2 Ebene 0 | WI-HW 60 | 1113Wa 0813147759 |  |  | m² | Zimmer- und Holzbauarbeiten | Wand | Innenwand 1-Schalig | WI-HW 60 |  |  | 0 | 1113HWa0812438082 |  |  |  | 0 |  |  | 47 | AllplanAttributes - Sicherheitsklasse: -
 | H2 Ebene 0 | WI-HW 60 | 1113Wa 0814130986 | yes |  | m² | Zimmer- und Holzbauarbeiten | Wand | Innenwand 1-Schalig | WI-HW 60 |  |  | 0 | 1113HWa0814130978 | NEW |  |  | 0 |  |  | 47 | AllplanAttributes - Sicherheitsklasse: -
 | H2 Ebene 0 | WI-HW 60 | 1113Wa 0814132495 | yes |  | m² | Zimmer- und Holzbauarbeiten | Wand | Innenwand 1-Schalig | WI-HW 60 |  |  | 0 | 1113HWa0814131982 | NEW |  |  | 0 |  |  | 47 | AllplanAttributes - Sicherheitsklasse: -
 | H2 Ebene 0 | WI-LB | 1113Wa 0812442711 |  |  | m² | Trockenbauarbeiten | Wand | Innenwand 1-Schalig | WI-LB |  |  | 0 | 1113HWa0812430771 |  |  |  | 0 |  |  | 0 | AllplanAttributes - Ortscode_Geschoßbezeichnung: E00; W_Deckenanschluss: Gleitender Deckenanschluss Fall 01; ash_W_Trockenbau_Qualitäten: 1b; Sicherheitsklasse: -
 | H2 Ebene 0 | Installationsraum | 1113Wa 0812463424 | yes |  | m² | Trockenbauarbeiten | Wand | Installationswand | Installationsraum |  |  | 0 | 1113HWa0812463423 | NEW |  |  | 0 |  |  | 0 | AllplanAttributes - Sicherheitsklasse: -
 | H2 Ebene 0 | WI-VS | 1113Wa 0812463425 | yes |  | m² | Trockenbauarbeiten | Wand | Installationswand | WI-VS |  |  | 0 | 1113HWa0812463423 | NEW |  |  | 0 |  |  | 0 | AllplanAttributes - W_Deckenanschluss: Gleitender Deckenanschluss Fall 01; ash_W_Trockenbau_Qualitäten: 2; Sicherheitsklasse: -
 | H2 Ebene 0 | WI-LB | 1113Wa 0812442706 |  |  | m² | Trockenbauarbeiten | Wand | Innenwand 1-Schalig | WI-LB |  |  | 0 | 1113HWa0812440867 |  |  |  | 0 |  |  | 0 | AllplanAttributes - Ortscode_Geschoßbezeichnung: E00; W_Deckenanschluss: Gleitender Deckenanschluss Fall 01; ash_W_Trockenbau_Qualitäten: 1b; Sicherheitsklasse: -
 | H2 Ebene 0 | WI-HW 60 | 1113Wa 0812443620 |  |  | m² | Zimmer- und Holzbauarbeiten | Wand | Innenwand 1-Schalig | WI-HW 60 |  |  | 0 | 1113HWa0812440865 |  |  |  | 0 |  |  | 0 | AllplanAttributes - Sicherheitsklasse: -
 | H2 Ebene 0 | WI-HW 60 | 1113Wa 0812446747 | yes |  | m² | Zimmer- und Holzbauarbeiten | Wand | Innenwand 1-Schalig | WI-HW 60 |  |  | 0 | 1113HWa0812442199 | NEW |  |  | 0 |  |  | 47 | AllplanAttributes - Sicherheitsklasse: -
 | H2 Ebene 0 | WI-HW 60 | 1113Wa 0814136219 | yes |  | m² | Zimmer- und Holzbauarbeiten | Wand | Innenwand 1-Schalig | WI-HW 60 |  |  | 0 | 1113HWa0814136209 | NEW |  |  | 0 |  |  | 47 | AllplanAttributes - Sicherheitsklasse: -
 | H2 Ebene 0 | WI-LB | 1113Wa 0814136246 | yes |  | m² | Trockenbauarbeiten | Wand | Innenwand 1-Schalig | WI-LB |  |  | 0 | 1113HWa0814136209 | NEW |  |  | 0 |  |  | 47 | AllplanAttributes - ash_W_Trockenbau_Qualitäten: 6; Sicherheitsklasse: -
 | H2 Ebene 0 | WI-HW 60 | 1113Wa 0814133525 |  |  | m² | Zimmer- und Holzbauarbeiten | Wand | Innenwand 1-Schalig | WI-HW 60 |  |  | 0 | 1113HWa0814133155 |  |  |  | 0 |  |  | 47 | AllplanAttributes - Sicherheitsklasse: -
 | H2 Ebene 0 | WI-LB | 1113Wa 0814133523 |  |  | m² | Trockenbauarbeiten | Wand | Innenwand 1-Schalig | WI-LB |  |  | 0 | 1113HWa0814133155 |  |  |  | 0 |  |  | 47 | AllplanAttributes - ash_W_Trockenbau_Qualitäten: 6; Sicherheitsklasse: -
 | H2 Ebene 0 | WI-HW 60 | 1113Wa 0814137443 | yes |  | m² | Zimmer- und Holzbauarbeiten | Wand | Innenwand 1-Schalig | WI-HW 60 |  |  | 0 | 1113HWa0814137067 | NEW |  |  | 0 |  |  | 47 | AllplanAttributes - Sicherheitsklasse: -
 | H2 Ebene 0 | WI-HW 60 | 1113Wa 0814141545 |  |  | m² | Zimmer- und Holzbauarbeiten | Wand | Innenwand 1-Schalig | WI-HW 60 |  |  | 0 | 1113HWa0814141470 |  |  |  | 0 |  |  | 47 | AllplanAttributes - Sicherheitsklasse: -
 | H2 Ebene 0 | WI-LB | 1113Wa 0814141543 |  |  | m² | Trockenbauarbeiten | Wand | Innenwand 1-Schalig | WI-LB |  |  | 0 | 1113HWa0814141470 |  |  |  | 0 |  |  | 47 | AllplanAttributes - ash_W_Trockenbau_Qualitäten: 6; Sicherheitsklasse: -
 | H2 Ebene 0 | WI-HW 60 | 1113Wa 0814140866 | yes |  | m² | Zimmer- und Holzbauarbeiten | Wand | Innenwand 1-Schalig | WI-HW 60 |  |  | 0 | 1113HWa0814140574 | NEW |  |  | 0 |  |  | 47 | AllplanAttributes - Sicherheitsklasse: -
 | H2 Ebene 0 | WI-HW 60 | 1113Wa 0814142127 |  |  | m² | Zimmer- und Holzbauarbeiten | Wand | Innenwand 1-Schalig | WI-HW 60 |  |  | 0 | 1113HWa0814141886 |  |  |  | 0 |  |  | 47 | AllplanAttributes - Sicherheitsklasse: -
 | H2 Ebene 0 | WI-LB | 1113Wa 0814142124 |  |  | m² | Trockenbauarbeiten | Wand | Innenwand 1-Schalig | WI-LB |  |  | 0 | 1113HWa0814141886 |  |  |  | 0 |  |  | 47 | AllplanAttributes - ash_W_Trockenbau_Qualitäten: 6; Sicherheitsklasse: -
 | H2 Ebene 0 | WI-HW 60 | 1113Wa 0814143160 |  |  | m² | Zimmer- und Holzbauarbeiten | Wand | Innenwand 1-Schalig | WI-HW 60 |  |  | 0 | 1113HWa0814142996 |  |  |  | 0 |  |  | 47 | AllplanAttributes - Sicherheitsklasse: -
 | H2 Ebene 0 | WI-LB | 1113Wa 0814143158 |  |  | m² | Trockenbauarbeiten | Wand | Innenwand 1-Schalig | WI-LB |  |  | 0 | 1113HWa0814142996 |  |  |  | 0 |  |  | 47 | AllplanAttributes - ash_W_Trockenbau_Qualitäten: 6; Sicherheitsklasse: -
 | H2 Ebene 0 | WI-HW 60 | 1113Wa 0812440280 |  |  | m² | Zimmer- und Holzbauarbeiten | Wand | Innenwand 1-Schalig | WI-HW 60 |  |  | 0 | 1113HWa0812425480 |  |  |  | 0 |  |  | 47 | AllplanAttributes - Sicherheitsklasse: -
 | H2 Ebene 0 | WI-LB | 1113Wa 0813143716 |  |  | m² | Trockenbauarbeiten | Wand | Innenwand 1-Schalig | WI-LB |  |  | 0 | 1113HWa0812425480 |  |  |  | 0 |  |  | 47 | AllplanAttributes - ash_W_Trockenbau_Qualitäten: 6; Sicherheitsklasse: -
 | H2 Ebene 0 | WI-HW 60 | 1113Wa 0814143482 | yes |  | m² | Zimmer- und Holzbauarbeiten | Wand | Innenwand 1-Schalig | WI-HW 60 |  |  | 0 | 1113HWa0814143405 | NEW |  |  | 0 |  |  | 47 | AllplanAttributes - Sicherheitsklasse: -
 | H2 Ebene 0 | WI-LB | 1113Wa 0812443219 |  |  | m² | Trockenbauarbeiten | Wand | Innenwand 1-Schalig | WI-LB |  |  | 0 | 1113HWa0812425627 |  |  |  | 0 |  |  | 47 | AllplanAttributes - Ortscode_Geschoßbezeichnung: E00; W_Deckenanschluss: Gleitender Deckenanschluss Fall 01; ash_W_Trockenbau_Qualitäten: 1b; Sicherheitsklasse: -
 | H2 Ebene 0 | WI-LB | 1113Wa 0813518673 |  |  | m² | Trockenbauarbeiten | Wand | Innenwand 1-Schalig | WI-LB |  |  | 0 | 1113HWa0813518388 |  |  |  | 0 |  |  | 47 | AllplanAttributes - ash_W_Trockenbau_Qualitäten: 8; Sicherheitsklasse: -
 | H2 Ebene 0 | Installationsraum | 1113Wa 0813518672 |  |  | m² | Trockenbauarbeiten | Wand | Innenwand 1-Schalig | Installationsraum |  |  | 0 | 1113HWa0813518388 |  |  |  | 0 |  |  | 47 | AllplanAttributes - Sicherheitsklasse: -
 | H2 Ebene 0 | WI-HW 60 | 1113Wa 0813518675 |  |  | m² | Zimmer- und Holzbauarbeiten | Wand | Innenwand 1-Schalig | WI-HW 60 |  |  | 0 | 1113HWa0813518388 |  |  |  | 0 |  |  | 47 | AllplanAttributes - Sicherheitsklasse: -
 | H2 Ebene 0 | WI-HW 60 | 1113Wa 0814144231 | yes |  | m² | Zimmer- und Holzbauarbeiten | Wand | Innenwand 1-Schalig | WI-HW 60 |  |  | 0 | 1113HWa0814144230 | NEW |  |  | 0 |  |  | 47 | AllplanAttributes - Sicherheitsklasse: -
 | H2 Ebene 0 | WI-IW | 1113Wa 0814144095 | yes |  | m² | Trockenbauarbeiten | Wand | Installationswand | WI-IW |  |  | 0 | 1113HWa0814144094 | NEW |  |  | 0 |  |  | 47 | AllplanAttributes - W_Deckenanschluss: Gleitender Deckenanschluss Fall 01; ash_W_Trockenbau_Qualitäten: 19; Sicherheitsklasse: -
 | H2 Ebene 0 | Installationsraum | 1113Wa 0814144096 | yes |  | m² | Trockenbauarbeiten | Wand | Installationswand | Installationsraum |  |  | 0 | 1113HWa0814144094 | NEW |  |  | 0 |  |  | 0 | AllplanAttributes - Sicherheitsklasse: -
 | H2 Ebene 0 | WI-IW | 1113Wa 0814144097 | yes |  | m² | Trockenbauarbeiten | Wand | Installationswand | WI-IW |  |  | 0 | 1113HWa0814144094 | NEW |  |  | 0 |  |  | 47 | AllplanAttributes - W_Deckenanschluss: Gleitender Deckenanschluss Fall 01; ash_W_Trockenbau_Qualitäten: 19; Sicherheitsklasse: -
 | H2 Ebene 0 | WI-IW | 1113Wa 0814144356 | yes |  | m² | Trockenbauarbeiten | Wand | Installationswand | WI-IW |  |  | 0 | 1113HWa0814144355 | NEW |  |  | 0 |  |  | 47 | AllplanAttributes - W_Deckenanschluss: Gleitender Deckenanschluss Fall 01; ash_W_Trockenbau_Qualitäten: 19; Sicherheitsklasse: -
 | H2 Ebene 0 | WI-LB | 1113Wa 0814145103 |  |  | m² | Trockenbauarbeiten | Wand | Innenwand 1-Schalig | WI-LB |  |  | 0 | 1113HWa0814145102 |  |  |  | 0 |  |  | 47 | AllplanAttributes - ash_W_Trockenbau_Qualitäten: 6; Sicherheitsklasse: -
 | H2 Ebene 0 | WI-IW | 1113Wa 0814145505 | yes |  | m² | Trockenbauarbeiten | Wand | Installationswand | WI-IW |  |  | 0 | 1113HWa0814145504 | NEW |  |  | 0 |  |  | 0 | AllplanAttributes - W_Deckenanschluss: Gleitender Deckenanschluss Fall 01; ash_W_Trockenbau_Qualitäten: 2; Sicherheitsklasse: -
 | H2 Ebene 0 | Installationsraum | 1113Wa 0814145506 | yes |  | m² | Trockenbauarbeiten | Wand | Installationswand | Installationsraum |  |  | 0 | 1113HWa0814145504 | NEW |  |  | 0 |  |  | 0 | AllplanAttributes - Sicherheitsklasse: -
 | H2 Ebene 0 | WI-IW | 1113Wa 0814135181 | yes |  | m² | Trockenbauarbeiten | Wand | Installationswand | WI-IW |  |  | 0 | 1113HWa0814135180 | NEW |  |  | 0 |  |  | 0 | AllplanAttributes - W_Deckenanschluss: Gleitender Deckenanschluss Fall 01; ash_W_Trockenbau_Qualitäten: 11; Sicherheitsklasse: -
 | H2 Ebene 0 | Installationsraum | 1113Wa 0814135182 | yes |  | m² | Trockenbauarbeiten | Wand | Installationswand | Installationsraum |  |  | 0 | 1113HWa0814135180 | NEW |  |  | 0 |  |  | 0 | AllplanAttributes - Sicherheitsklasse: -
 | H2 Ebene 0 | WI-LB | 1113Wa 0814145526 | yes |  | m² | Trockenbauarbeiten | Wand | Installationswand | WI-LB |  |  | 0 | 1113HWa0814135180 | NEW |  |  | 0 |  |  | 0 | AllplanAttributes - W_Deckenanschluss: Gleitender Deckenanschluss Fall 01; ash_W_Trockenbau_Qualitäten: 11; Sicherheitsklasse: -
 | H2 Ebene 0 | WI-LB | 1113Wa 0814153235 | yes |  | m² | Trockenbauarbeiten | Wand | Innenwand 1-Schalig | WI-LB |  |  | 0 | 1113HWa0814153234 | NEW |  |  | 0 |  |  | 47 | AllplanAttributes - W_Deckenanschluss: Gleitender Deckenanschluss Fall 01; ash_W_Trockenbau_Qualitäten: 1b; Sicherheitsklasse: -
 | H2 Ebene 0 | WI-LB | 1113Wa 0812444047 |  |  | m² | Trockenbauarbeiten | Wand | Innenwand 1-Schalig | WI-LB |  |  | 0 | 1113HWa0812443364 |  |  |  | 0 |  |  | 47 | AllplanAttributes - Ortscode_Geschoßbezeichnung: E00; W_Deckenanschluss: Gleitender Deckenanschluss Fall 01; ash_W_Trockenbau_Qualitäten: 1b; Sicherheitsklasse: -
 | H2 Ebene 0 | WI-LB | 1113Wa 0814153336 | yes |  | m² | Trockenbauarbeiten | Wand | Innenwand 1-Schalig | WI-LB |  |  | 0 | 1113HWa0814153335 | NEW |  |  | 0 |  |  | 47 | AllplanAttributes - W_Deckenanschluss: Gleitender Deckenanschluss Fall 01; Sicherheitsklasse: -
 | H2 Ebene 0 | WI-HW 60 | 1113Wa 0813813739 | yes |  | m² | Zimmer- und Holzbauarbeiten | Wand | Innenwand 1-Schalig | WI-HW 60 |  |  | 0 | 1113HWa0813813728 | NEW |  |  | 0 |  |  | 0 | AllplanAttributes - Sicherheitsklasse: -
 | H2 Ebene 0 | WI-HW 60 | 1113Wa 0812498502 | yes |  | m² | Zimmer- und Holzbauarbeiten | Wand | Innenwand 1-Schalig | WI-HW 60 |  |  | 0 | 1113HWa0812498501 | NEW |  |  | 0 |  |  | 0 | AllplanAttributes - Sicherheitsklasse: -
 | H2 Ebene 0 | WI-IW | 1113Wa 0814153658 | yes |  | m² | Trockenbauarbeiten | Wand | Installationswand | WI-IW |  |  | 0 | 1113HWa0814153657 | NEW |  |  | 0 |  |  | 47 | AllplanAttributes - W_Deckenanschluss: Gleitender Deckenanschluss Fall 01; ash_W_Trockenbau_Qualitäten: 14; Sicherheitsklasse: -
 | H2 Ebene 0 | Installationsraum | 1113Wa 0814153659 | yes |  | m² | Trockenbauarbeiten | Wand | Installationswand | Installationsraum |  |  | 0 | 1113HWa0814153657 | NEW |  |  | 0 |  |  | 0 | AllplanAttributes - Sicherheitsklasse: -
 | H2 Ebene 0 | WI-IW | 1113Wa 0814153660 | yes |  | m² | Trockenbauarbeiten | Wand | Installationswand | WI-IW |  |  | 0 | 1113HWa0814153657 | NEW |  |  | 0 |  |  | 47 | AllplanAttributes - W_Deckenanschluss: Gleitender Deckenanschluss Fall 01; ash_W_Trockenbau_Qualitäten: 14; Sicherheitsklasse: -
 | H2 Ebene 0 | WI-IW | 1113Wa 0814153790 | yes |  | m² | Trockenbauarbeiten | Wand | Installationswand | WI-IW |  |  | 0 | 1113HWa0814153787 | NEW |  |  | 0 |  |  | 47 | AllplanAttributes - W_Deckenanschluss: Gleitender Deckenanschluss Fall 01; ash_W_Trockenbau_Qualitäten: 14; Sicherheitsklasse: -
 | H2 Ebene 0 | Installationsraum | 1113Wa 0814153789 | yes |  | m² | Trockenbauarbeiten | Wand | Installationswand | Installationsraum |  |  | 0 | 1113HWa0814153787 | NEW |  |  | 0 |  |  | 0 | AllplanAttributes - Sicherheitsklasse: -
 | H2 Ebene 0 | WI-IW | 1113Wa 0814153791 | yes |  | m² | Trockenbauarbeiten | Wand | Installationswand | WI-IW |  |  | 0 | 1113HWa0814153787 | NEW |  |  | 0 |  |  | 47 | AllplanAttributes - W_Deckenanschluss: Gleitender Deckenanschluss Fall 01; ash_W_Trockenbau_Qualitäten: 14; Sicherheitsklasse: -
 | H2 Ebene 0 | Installationsraum | 1113Wa 0812446835 | yes |  | m² | Trockenbauarbeiten | Wand | Installationswand | Installationsraum |  |  | 0 | 1113HWa0812435307 | NEW |  |  | 0 |  |  | 0 | AllplanAttributes - Sicherheitsklasse: -
 | H2 Ebene 0 | WI-VS | 1113Wa 0812446831 | yes |  | m² | Trockenbauarbeiten | Wand | Installationswand | WI-VS |  |  | 0 | 1113HWa0812435307 | NEW |  |  | 0 |  |  | 0 | AllplanAttributes - W_Deckenanschluss: Gleitender Deckenanschluss Fall 01; ash_W_Trockenbau_Qualitäten: 18; Sicherheitsklasse: -
 | H2 Ebene 0 | WI-IW | 1113Wa 0812957796 | yes |  | m² | Trockenbauarbeiten | Wand | Installationswand | WI-IW |  |  | 0 | 1113HWa0812957794 | NEW |  |  | 0 |  |  | 0 | AllplanAttributes - W_Deckenanschluss: Gleitender Deckenanschluss Fall 01; ash_W_Trockenbau_Qualitäten: 18; Sicherheitsklasse: -
 | H2 Ebene 0 | WI-IW | 1113Wa 0812464251 | yes |  | m² | Trockenbauarbeiten | Wand | Installationswand | WI-IW |  |  | 0 | 1113HWa0812464250 | NEW |  |  | 0 |  |  | 0 | AllplanAttributes - W_Deckenanschluss: Gleitender Deckenanschluss Fall 01; ash_W_Trockenbau_Qualitäten: 18; Sicherheitsklasse: -
 | H2 Ebene 0 | Installationsraum | 1113Wa 0812464252 | yes |  | m² | Trockenbauarbeiten | Wand | Installationswand | Installationsraum |  |  | 0 | 1113HWa0812464250 | NEW |  |  | 0 |  |  | 0 | AllplanAttributes - Sicherheitsklasse: -
 | H2 Ebene 0 | WI-IW | 1113Wa 0812464273 | yes |  | m² | Trockenbauarbeiten | Wand | Installationswand | WI-IW |  |  | 0 | 1113HWa0812464272 | NEW |  |  | 0 |  |  | 0 | AllplanAttributes - W_Deckenanschluss: Gleitender Deckenanschluss Fall 01; ash_W_Trockenbau_Qualitäten: 18; Sicherheitsklasse: -
 | H2 Ebene 0 | WI-LB | 1113Wa 0812437339 | yes |  | m² | Trockenbauarbeiten | Wand | Innenwand 1-Schalig | WI-LB |  |  | 0 | 1113HWa0812434425 |  |  |  | 0 | AllplanAttributes - Ortscode_Geschoßbezeichnung: E00; W_Deckenanschluss: Gleitender Deckenanschluss Fall 01; ash_W_Trockenbau_Qualitäten: 4; Sicherheitsklasse: -
 | H2 Ebene 0 | WI-LB | 1113Wa 0812446956 | yes |  | m² | Trockenbauarbeiten | Wand | Innenwand 1-Schalig | WI-LB |  |  | 0 | 1113HWa0812434668 |  |  |  | 0 |  |  | 52 | AllplanAttributes - Ortscode_Geschoßbezeichnung: E00; W_Deckenanschluss: Gleitender Deckenanschluss Fall 01; ash_W_Trockenbau_Qualitäten: 4; Sicherheitsklasse: -
 | H2 Ebene 0 | WI-IW | 1113Wa 0812464511 | yes |  | m² | Trockenbauarbeiten | Wand | Installationswand | WI-IW |  |  | 0 | 1113HWa0812464506 | NEW |  |  | 0 |  |  | 0 | AllplanAttributes - W_Deckenanschluss: Gleitender Deckenanschluss Fall 01; ash_W_Trockenbau_Qualitäten: 18; Sicherheitsklasse: -
 | H2 Ebene 0 | Installationsraum | 1113Wa 0812464512 | yes |  | m² | Trockenbauarbeiten | Wand | Installationswand | Installationsraum |  |  | 0 | 1113HWa0812464506 | NEW |  |  | 0 |  |  | 0 | AllplanAttributes - Sicherheitsklasse: -
 | H2 Ebene 0 | WI-IW | 1113Wa 0812464234 | yes |  | m² | Trockenbauarbeiten | Wand | Installationswand | WI-IW |  |  | 0 | 1113HWa0812464233 | NEW |  |  | 0 |  |  | 0 | AllplanAttributes - W_Deckenanschluss: Gleitender Deckenanschluss Fall 01; ash_W_Trockenbau_Qualitäten: 18; Sicherheitsklasse: -
 | H2 Ebene 0 | Installationsraum | 1113Wa 0812464235 | yes |  | m² | Trockenbauarbeiten | Wand | Installationswand | Installationsraum |  |  | 0 | 1113HWa0812464233 | NEW |  |  | 0 |  |  | 0 | AllplanAttributes - Sicherheitsklasse: -
 | H2 Ebene 0 | WI-LB | 1113Wa 0814157555 | yes |  | m² | Trockenbauarbeiten | Wand | Innenwand 1-Schalig | WI-LB |  |  | 0 | 1113HWa0814157554 | NEW |  |  | 0 |  |  | 47 | AllplanAttributes - ash_W_Trockenbau_Qualitäten: 6; Sicherheitsklasse: -
 | H2 Ebene 0 | WI-HW 60 | 1113Wa 0812440282 | yes |  | m² | Zimmer- und Holzbauarbeiten | Wand | Innenwand 1-Schalig | WI-HW 60 |  |  | 0 | 1113HWa0812438500 | NEW |  |  | 0 |  |  | 0 | AllplanAttributes - Sicherheitsklasse: -
 | H2 Ebene 0 | WI-HW 60 | 1113Wa 0812440284 | yes |  | m² | Zimmer- und Holzbauarbeiten | Wand | Innenwand 1-Schalig | WI-HW 60 |  |  | 0 | 1113HWa0812438506 | NEW |  |  | 0 |  |  | 0 | AllplanAttributes - Sicherheitsklasse: -
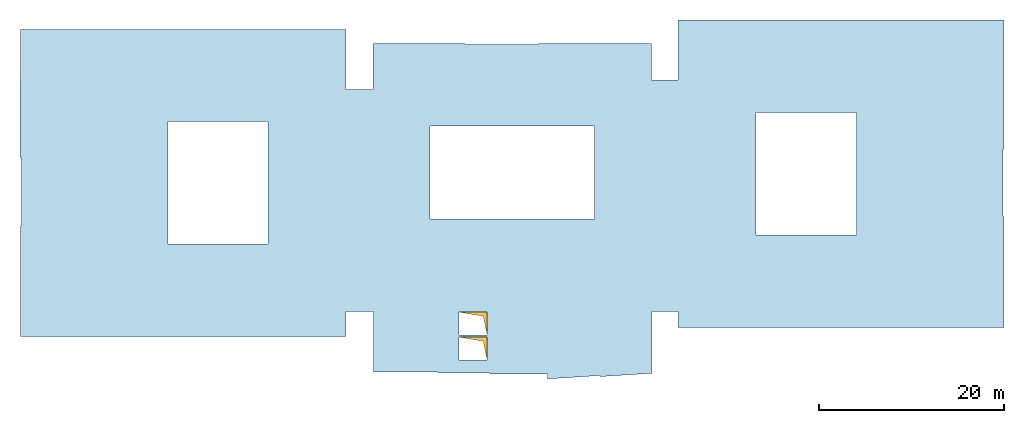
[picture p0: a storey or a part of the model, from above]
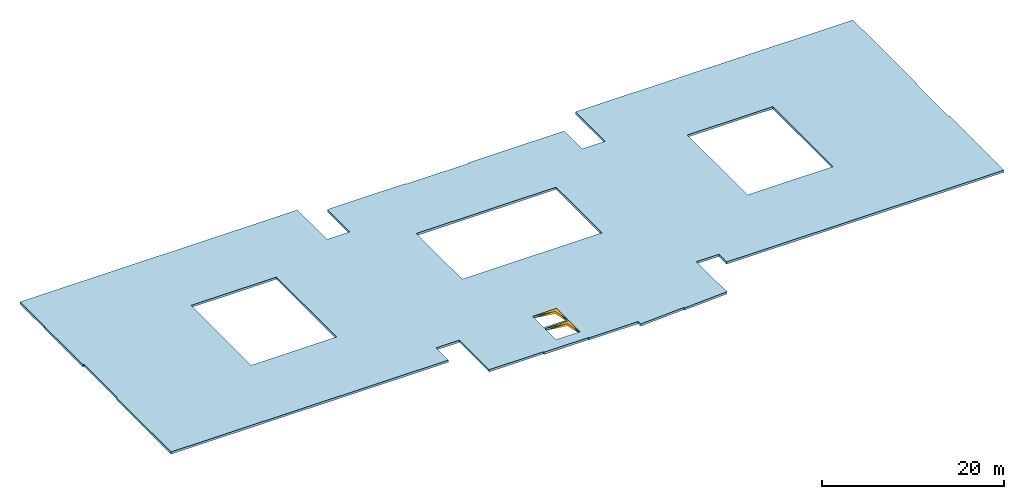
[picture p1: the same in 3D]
Properties of the parts of a building model (IFC4), part 75 of 80

# IfcWall (6826)
Name | In | Material | Allright_Bauteil_ID | 2D Interaktion | Codetext | Abrechnungsart | Gewerk | Objektname | Bezeichnung | AllplanAttributes, Material | Typ = SurfaceSpreadOfFlame | Brandschutzklasse | OKFF | P_ID | Status | LoadBearing | IsExternal | FireRating | ThermalTransmittance (W/K/m2) | Combustible | AcousticRating | Compartmentation | Reference
 | H2 Ebene 0 | WI-IW | 1113Wa 0812464601 | yes |  | m² | Trockenbauarbeiten | Wand | Installationswand | WI-IW |  |  | 0 | 1113HWa0812464600 | NEW |  |  | 0 |  |  | 0 | AllplanAttributes - W_Deckenanschluss: Gleitender Deckenanschluss Fall 01; ash_W_Trockenbau_Qualitäten: 18; Sicherheitsklasse: -
 | H2 Ebene 0 | Installationsraum | 1113Wa 0812464602 | yes |  | m² | Trockenbauarbeiten | Wand | Installationswand | Installationsraum |  |  | 0 | 1113HWa0812464600 | NEW |  |  | 0 |  |  | 0 | AllplanAttributes - Sicherheitsklasse: -
 | H2 Ebene 0 | WI-LB | 1113Wa 0814158424 |  |  | m² | Trockenbauarbeiten | Wand | Innenwand 1-Schalig | WI-LB |  |  | 0 | 1113HWa0814158284 | OTHER |  |  | 0 |  |  | 47 | AllplanAttributes - ash_W_Trockenbau_Qualitäten: 8; Sicherheitsklasse: -
 | H2 Ebene 0 | Installationsraum | 1113Wa 0814158421 | yes |  | m² | Trockenbauarbeiten | Wand | Innenwand 1-Schalig | Installationsraum |  |  | 0 | 1113HWa0814158284 | NEW |  |  | 0 |  |  | 47 | AllplanAttributes - Sicherheitsklasse: -
 | H2 Ebene 0 | WI-HW 60 | 1113Wa 0814158423 | yes |  | m² | Zimmer- und Holzbauarbeiten | Wand | Innenwand 1-Schalig | WI-HW 60 |  |  | 0 | 1113HWa0814158284 | NEW |  |  | 0 |  |  | 47 | AllplanAttributes - Sicherheitsklasse: -
 | H2 Ebene 0 | WI-HW 60 | 1113Wa 0813446098 | yes |  | m² | Zimmer- und Holzbauarbeiten | Wand | Innenwand 1-Schalig | WI-HW 60 |  |  | 0 | 1113HWa0813446091 |  |  |  | 0 |  |  | 47 | AllplanAttributes - Sicherheitsklasse: -
 | H2 Ebene 0 | Installationsraum | 1113Wa 0813446093 | yes |  | m² | Trockenbauarbeiten | Wand | Innenwand 1-Schalig | Installationsraum |  |  | 0 | 1113HWa0813446091 |  |  |  | 0 |  |  | 0 | AllplanAttributes - Sicherheitsklasse: -
 | H2 Ebene 0 | WI-LB | 1113Wa 0813446095 |  |  | m² | Trockenbauarbeiten | Wand | Innenwand 1-Schalig | WI-LB |  |  | 0 | 1113HWa0813446091 |  |  |  | 0 |  |  | 47 | AllplanAttributes - ash_W_Trockenbau_Qualitäten: 6; Sicherheitsklasse: -
 | H2 Ebene 0 | WI-LB | 1113Wa 0814028124 | yes |  | m² | Trockenbauarbeiten | Wand | Innenwand 1-Schalig | WI-LB |  |  | 0 | 1113HWa0814028122 | NEW |  |  | 0 |  |  | 47 | AllplanAttributes - W_Deckenanschluss: Gleitender Deckenanschluss Fall 01; ash_W_Trockenbau_Qualitäten: 1a; Sicherheitsklasse: -
 | H2 Ebene 0 | WI-LB | 1113Wa 0814028752 | yes |  | m² | Trockenbauarbeiten | Wand | Innenwand 1-Schalig | WI-LB |  |  | 0 | 1113HWa0814028750 | NEW |  |  | 0 |  |  | 47 | AllplanAttributes - W_Deckenanschluss: Gleitender Deckenanschluss Fall 01; ash_W_Trockenbau_Qualitäten: 1a; Sicherheitsklasse: -
 | H2 Ebene 0 | WI-LB | 1113Wa 0814161107 | yes |  | m² | Trockenbauarbeiten | Wand | Innenwand 1-Schalig | WI-LB |  |  | 0 | 1113HWa0814161106 |  |  |  | 0 |  |  | 47 | AllplanAttributes - W_Deckenanschluss: Gleitender Deckenanschluss Fall 01; ash_W_Trockenbau_Qualitäten: 1b; Sicherheitsklasse: -
 | H2 Ebene 0 | WI-LB | 1113Wa 0814161124 | yes |  | m² | Trockenbauarbeiten | Wand | Innenwand 1-Schalig | WI-LB |  |  | 0 | 1113HWa0814161123 | NEW |  |  | 0 |  |  | 47 | AllplanAttributes - W_Deckenanschluss: Gleitender Deckenanschluss Fall 01; ash_W_Trockenbau_Qualitäten: 1b; Sicherheitsklasse: -
 | H2 Ebene 0 | WI-LB | 1113Wa 0812812970 |  |  | m² | Trockenbauarbeiten | Wand | Innenwand 1-Schalig | WI-LB |  |  | 0 | 1113HWa0812812969 |  |  |  | 0 |  |  | 47 | AllplanAttributes - ash_W_Trockenbau_Qualitäten: 6; Sicherheitsklasse: -
 | H2 Ebene 0 | WI-LB | 1113Wa 0812842569 |  |  | m² | Trockenbauarbeiten | Wand | Innenwand 1-Schalig | WI-LB |  |  | 0 | 1113HWa0812842568 |  |  |  | 0 | AllplanAttributes - ash_W_Trockenbau_Qualitäten: 6; Sicherheitsklasse: -
 | H2 Ebene 0 | WI-LB | 1113Wa 0812841138 |  |  | m² | Trockenbauarbeiten | Wand | Innenwand 1-Schalig | WI-LB |  |  | 0 | 1113HWa0812841137 |  |  |  | 0 | AllplanAttributes - ash_W_Trockenbau_Qualitäten: 9; Sicherheitsklasse: -
 | H2 Ebene 0 | WI-LB | 1113Wa 0812542270 |  |  | m² | Trockenbauarbeiten | Wand | Außenwand 1-Schalig | WI-LB |  |  | 0 | 1113HWa0812542253 | OTHER |  |  | 0 |  |  | 47 | AllplanAttributes - ash_W_Trockenbau_Qualitäten: 9; Sicherheitsklasse: -
 | H2 Ebene 0 | WI-STB | 1113Wa 0812842005 | yes |  | m² | Zimmer- und Holzbauarbeiten | Wand | Außenwand 1-Schalig | WI-STB |  |  | 0 | 1113HWa0812542253 | NEW |  |  | 0 |  |  | 47 | AllplanAttributes - Sicherheitsklasse: -
 | H2 Ebene 0 | WI-LB | 1113Wa 0812839961 |  |  | m² | Trockenbauarbeiten | Wand | Innenwand 1-Schalig | WI-LB |  |  | 0 | 1113HWa0812839960 |  |  |  | 0 |  |  | 47 | AllplanAttributes - ash_W_Trockenbau_Qualitäten: 9; Sicherheitsklasse: -
 | H2 Ebene 0 | WI-LB | 1113Wa 0812841148 |  |  | m² | Trockenbauarbeiten | Wand | Innenwand 1-Schalig | WI-LB |  |  | 0 | 1113HWa0812841147 |  |  |  | 0 | AllplanAttributes - ash_W_Trockenbau_Qualitäten: 9; Sicherheitsklasse: -
 | H2 Ebene 0 | WI-LB | 1113Wa 0812841825 |  |  | m² | Trockenbauarbeiten | Wand | Innenwand 1-Schalig | WI-LB |  |  | 0 | 1113HWa0812841824 |  |  |  | 0 | AllplanAttributes - ash_W_Trockenbau_Qualitäten: 9; Sicherheitsklasse: -
 | H2 Ebene 0 | WI-LB | 1113Wa 0812809798 |  |  | m² | Trockenbauarbeiten | Wand | Innenwand 1-Schalig | WI-LB |  |  | 0 | 1113HWa0812809797 |  |  |  | 0 | AllplanAttributes - ash_W_Trockenbau_Qualitäten: 9; Sicherheitsklasse: -
 | H2 Ebene 0 | WI-LB | 1113Wa 0812839979 |  |  | m² | Trockenbauarbeiten | Wand | Innenwand 1-Schalig | WI-LB |  |  | 0 | 1113HWa0812839978 |  |  |  | 0 |  |  | 47 | AllplanAttributes - ash_W_Trockenbau_Qualitäten: 9; Sicherheitsklasse: -
 | H2 Ebene 0 | WI-LB | 1113Wa 0812842178 |  |  | m² | Trockenbauarbeiten | Wand | Innenwand 1-Schalig | WI-LB |  |  | 0 | 1113HWa0812842177 |  |  |  | 0 |  |  | 47 | AllplanAttributes - ash_W_Trockenbau_Qualitäten: 9; Sicherheitsklasse: -
 | H2 Ebene 0 | WI-LB | 1113Wa 0812842408 |  |  | m² | Trockenbauarbeiten | Wand | Innenwand 1-Schalig | WI-LB |  |  | 0 | 1113HWa0812842407 |  |  |  | 0 | AllplanAttributes - ash_W_Trockenbau_Qualitäten: 9; Sicherheitsklasse: -
 | H2 Ebene 0 | WI-LB | 1113Wa 0812842157 |  |  | m² | Trockenbauarbeiten | Wand | Innenwand 1-Schalig | WI-LB |  |  | 0 | 1113HWa0812842156 |  |  |  | 0 | AllplanAttributes - ash_W_Trockenbau_Qualitäten: 9; Sicherheitsklasse: -
 | H2 Ebene 0 | WI-LB | 1113Wa 0812842430 |  |  | m² | Trockenbauarbeiten | Wand | Innenwand 1-Schalig | WI-LB |  |  | 0 | 1113HWa0812842429 |  |  |  | 0 | AllplanAttributes - ash_W_Trockenbau_Qualitäten: 9; Sicherheitsklasse: -
 | H2 Ebene 0 | WI-LB | 1113Wa 0812846432 |  |  | m² | Trockenbauarbeiten | Wand | Innenwand 1-Schalig | WI-LB |  |  | 0 | 1113HWa0812846431 |  |  |  | 0 | AllplanAttributes - ash_W_Trockenbau_Qualitäten: 9; Sicherheitsklasse: -
 | H2 Ebene 0 | WI-LB | 1113Wa 0812841456 |  |  | m² | Trockenbauarbeiten | Wand | Innenwand 1-Schalig | WI-LB |  |  | 0 | 1113HWa0812841455 |  |  |  | 0 | AllplanAttributes - ash_W_Trockenbau_Qualitäten: 6; Sicherheitsklasse: -
 | H2 Ebene 0 | WI-LB | 1113Wa 0812842684 |  |  | m² | Trockenbauarbeiten | Wand | Innenwand 1-Schalig | WI-LB |  |  | 0 | 1113HWa0812842683 |  |  |  | 0 | AllplanAttributes - ash_W_Trockenbau_Qualitäten: 6; Sicherheitsklasse: -
 | H2 Ebene 0 | WI-LB | 1113Wa 0812841599 |  |  | m² | Trockenbauarbeiten | Wand | Innenwand 1-Schalig | WI-LB |  |  | 0 | 1113HWa0812841598 |  |  |  | 0 | AllplanAttributes - ash_W_Trockenbau_Qualitäten: 9; Sicherheitsklasse: -
 | H2 Ebene 0 | WI-LB | 1113Wa 0812842557 |  |  | m² | Trockenbauarbeiten | Wand | Innenwand 1-Schalig | WI-LB |  |  | 0 | 1113HWa0812842556 |  |  |  | 0 | AllplanAttributes - ash_W_Trockenbau_Qualitäten: 9; Sicherheitsklasse: -
 | H2 Ebene 0 | WI-LB | 1113Wa 0812846272 |  |  | m² | Trockenbauarbeiten | Wand | Innenwand 1-Schalig | WI-LB |  |  | 0 | 1113HWa0812846271 |  |  |  | 0 | AllplanAttributes - ash_W_Trockenbau_Qualitäten: 9; Sicherheitsklasse: -
 | H2 Ebene 0 | WI-LB | 1113Wa 0812842672 |  |  | m² | Trockenbauarbeiten | Wand | Innenwand 1-Schalig | WI-LB |  |  | 0 | 1113HWa0812842671 |  |  |  | 0 | AllplanAttributes - ash_W_Trockenbau_Qualitäten: 6; Sicherheitsklasse: -
 | H2 Ebene 0 | WI-LB | 1113Wa 0812494625 | yes |  | m² | Trockenbauarbeiten | Wand | Innenwand 1-Schalig | WI-LB |  |  | 0 | 1113HWa0812494623 |  |  |  | 0 |  |  | 0 | AllplanAttributes - Ortscode_Geschoßbezeichnung: E00; W_Deckenanschluss: Gleitender Deckenanschluss Fall 01; ash_W_Trockenbau_Qualitäten: 1b; Sicherheitsklasse: -
 | H2 Ebene 0 | WI-LB | 1113Wa 0812847587 |  |  | m² | Trockenbauarbeiten | Wand | Innenwand 1-Schalig | WI-LB |  |  | 0 | 1113HWa0812847586 |  |  |  | 0 | AllplanAttributes - ash_W_Trockenbau_Qualitäten: 6; Sicherheitsklasse: -
WV 1.1 | H2 Ebene 0 |  | 1113Sma0814160636 |  | VUK5 - Handlauf | St | Trockenbauarbeiten | SmartPart | WV 1.1 |  |  |  | 0.2 |  |  |  |  | - | AllplanAttributes - ash_W_Trockenbau_Qualitäten: 9; Text1: WA; UK: 0 m; OK: 0 m; V6: 0 m; V7: 0 m; V8: 0 m; V9: 0; Länge: 1.5 m; Dicke: 0.025 m; Höhe: 0.2 m; Programmversion: 3.1; Text3: 0; Plugin_Bezeichnung: MainObject; Plugin_Objektname: SmartPartCompressed; Version: 1.1; Abstand_Öffn_Unten: 0.9 m; ash T_Feuchtebeständigkeit: nein; Feuerwiderstandsklasse~: nein
 | H2 Ebene 0 | WI-LB | 1113Wa 0814167555 | yes |  | m² | Trockenbauarbeiten | Wand | Innenwand 1-Schalig | WI-LB |  |  | 0 | 1113HWa0814167554 |  |  |  | 0 | AllplanAttributes - ash_W_Trockenbau_Qualitäten: 9; Sicherheitsklasse: -
 | H2 Ebene 0 | WI-LB | 1113Wa 0814167875 | yes |  | m² | Trockenbauarbeiten | Wand | Innenwand 1-Schalig | WI-LB |  |  | 0 | 1113HWa0814167874 |  |  |  | 0 |  |  | 47 | AllplanAttributes - ash_W_Trockenbau_Qualitäten: 9; Sicherheitsklasse: -
 | H2 Ebene 0 | WI-LB | 1113Wa 0814167926 | yes |  | m² | Trockenbauarbeiten | Wand | Innenwand 1-Schalig | WI-LB |  |  | 0 | 1113HWa0814167924 |  |  |  | 0 | AllplanAttributes - ash_W_Trockenbau_Qualitäten: 9; Sicherheitsklasse: -
 | H2 Ebene 0 | WI-LB | 1113Wa 0814168106 | yes |  | m² | Trockenbauarbeiten | Wand | Innenwand 1-Schalig | WI-LB |  |  | 0 | 1113HWa0814168104 |  |  |  | 0 | AllplanAttributes - ash_W_Trockenbau_Qualitäten: 9; Sicherheitsklasse: -
 | H2 Ebene 0 | WI-LB | 1113Wa 0814168100 | yes |  | m² | Trockenbauarbeiten | Wand | Innenwand 1-Schalig | WI-LB |  |  | 0 | 1113HWa0814168099 |  |  |  | 0 | AllplanAttributes - ash_W_Trockenbau_Qualitäten: 9; Sicherheitsklasse: -
 | H2 Ebene 0 | WI-LB | 1113Wa 0814168982 | yes |  | m² | Trockenbauarbeiten | Wand | Innenwand 1-Schalig | WI-LB |  |  | 0 | 1113HWa0814168981 |  |  |  | 0 | AllplanAttributes - ash_W_Trockenbau_Qualitäten: 9; Sicherheitsklasse: -
 | H2 Ebene 0 | WI-LB | 1113Wa 0812543040 |  |  | m² | Trockenbauarbeiten | Wand | Innenwand 1-Schalig | WI-LB |  |  | 0 | 1113HWa0812543038 |  |  |  | 0 |  |  | 0 | AllplanAttributes - Ortscode_Geschoßbezeichnung: E00; W_Deckenanschluss: Gleitender Deckenanschluss Fall 01; ash_W_Trockenbau_Qualitäten: 13; Sicherheitsklasse: -
 | H2 Ebene 0 | WI-STB | 1113Wa 0812543042 | yes |  | m² | Zimmer- und Holzbauarbeiten | Wand | Außenwand 1-Schalig | WI-STB |  |  | 0 | 1113HWa0812543031 | NEW |  |  | 0 |  |  | 0 | AllplanAttributes - Ortscode_Geschoßbezeichnung: E00; Sicherheitsklasse: -
 | H2 Ebene 0 | WI-LB | 1113Wa 0814169149 | yes |  | m² | Trockenbauarbeiten | Wand | Innenwand 1-Schalig | WI-LB |  |  | 0 | 1113HWa0814169147 |  |  |  | 0 | AllplanAttributes - ash_W_Trockenbau_Qualitäten: 9; Sicherheitsklasse: -
WV 1.1 | H2 Ebene 0 |  | 1113Sma0814173356 |  | VUK1 - Feuerlöscher | St | Trockenbauarbeiten | SmartPart | WV 1.1 |  |  |  | 0.2 |  |  |  |  | - | AllplanAttributes - Text1: WA; UK: 0 m; OK: 0 m; V6: 0 m; V7: 0 m; V8: 0 m; V9: 0; Länge: 0.3 m; Dicke: 0.025 m; Höhe: 0.7 m; Programmversion: 3.1; Text3: 0; Plugin_Bezeichnung: MainObject; Plugin_Objektname: SmartPartCompressed; Version: 1.1; Abstand_Öffn_Unten: 0.85 m; ash T_Feuchtebeständigkeit: nein; Feuerwiderstandsklasse~: nein
WV 1.1 | H2 Ebene 0 |  | 1113Sma0814178347 |  | VUK1 - Feuerlöscher | St | Trockenbauarbeiten | SmartPart | WV 1.1 |  |  |  | 0.2 |  |  |  |  | - | AllplanAttributes - Text1: WA; UK: 0 m; OK: 0 m; V6: 0 m; V7: 0 m; V8: 0 m; V9: 0; Länge: 0.3 m; Dicke: 0.025 m; Höhe: 0.7 m; Programmversion: 3.1; Text3: 0; Plugin_Bezeichnung: MainObject; Plugin_Objektname: SmartPartCompressed; Version: 1.1; Abstand_Öffn_Unten: 0.85 m; ash T_Feuchtebeständigkeit: nein; Feuerwiderstandsklasse~: nein
WV 1.1 | H2 Ebene 0 |  | 1113Sma0814178372 |  | VUK1 - Feuerlöscher | St | Trockenbauarbeiten | SmartPart | WV 1.1 |  |  |  | 0.2 |  |  |  |  | - | AllplanAttributes - Text1: WA; UK: 0 m; OK: 0 m; V6: 0 m; V7: 0 m; V8: 0 m; V9: 0; Länge: 0.3 m; Dicke: 0.025 m; Höhe: 0.7 m; Programmversion: 3.1; Text3: 0; Plugin_Bezeichnung: MainObject; Plugin_Objektname: SmartPartCompressed; Version: 1.1; Abstand_Öffn_Unten: 0.85 m; ash T_Feuchtebeständigkeit: nein; Feuerwiderstandsklasse~: nein
 | H2 Ebene 0 | WI-LB | 1113Wa 0814178387 | yes |  | m² | Trockenbauarbeiten | Wand | Innenwand 1-Schalig | WI-LB |  |  | 0 | 1113HWa0814178386 | NEW |  |  | 0 |  |  | 0 | AllplanAttributes - W_Deckenanschluss: Gleitender Deckenanschluss Fall 01; ash_W_Trockenbau_Qualitäten: 1b; Sicherheitsklasse: -
 | H2 Ebene 0 | WI-LB | 1113Wa 0812437723 | yes |  | m² | Trockenbauarbeiten | Wand | Innenwand 1-Schalig | WI-LB |  |  | 0 | 1113HWa0812425484 |  |  |  | 0 |  |  | 0 | AllplanAttributes - Ortscode_Geschoßbezeichnung: E00; W_Deckenanschluss: Gleitender Deckenanschluss Fall 03; ash_W_Trockenbau_Qualitäten: 10a; Sicherheitsklasse: -
 | H2 Ebene 0 | WI-LB | 1113Wa 0812439336 | yes |  | m² | Trockenbauarbeiten | Wand | Innenwand 1-Schalig | WI-LB |  |  | 0 | 1113HWa0812425485 |  |  |  | 0 |  |  | 0 | AllplanAttributes - Ortscode_Geschoßbezeichnung: E00; W_Deckenanschluss: Gleitender Deckenanschluss Fall 03; ash_W_Trockenbau_Qualitäten: 10a; Sicherheitsklasse: -
 | H2 Ebene 0 | WI-LB | 1113Wa 0812439332 | yes |  | m² | Trockenbauarbeiten | Wand | Innenwand 1-Schalig | WI-LB |  |  | 0 | 1113HWa0812425486 |  |  |  | 0 |  |  | 0 | AllplanAttributes - Ortscode_Geschoßbezeichnung: E00; W_Deckenanschluss: Gleitender Deckenanschluss Fall 03; ash_W_Trockenbau_Qualitäten: 10a; Sicherheitsklasse: -
 | H2 Ebene 0 | WI-LB | 1113Wa 0812437627 | yes |  | m² | Trockenbauarbeiten | Wand | Innenwand 1-Schalig | WI-LB |  |  | 0 | 1113HWa0812430763 |  |  |  | 0 | AllplanAttributes - ash_W_Trockenbau_Qualitäten: 16; Sicherheitsklasse: -
 | H2 Ebene 0 | WI-HW 60 | 1113Wa 0813120192 | yes |  | m² | Zimmer- und Holzbauarbeiten | Wand | Innenwand 1-Schalig | WI-HW 60 |  |  | 0 | 1113HWa0812430763 |  |  |  | 0 |  |  | 0 | AllplanAttributes - Sicherheitsklasse: -
 | H2 Ebene 0 | WI-LB | 1113Wa 0812437388 | yes |  | m² | Trockenbauarbeiten | Wand | Außenwand 1-Schalig | WI-LB |  |  | 0 | 1113HWa0812425731 |  |  |  | 0 |  |  | 0 | AllplanAttributes - Ortscode_Geschoßbezeichnung: E00; W_Deckenanschluss: Gleitender Deckenanschluss Fall 01; ash_W_Trockenbau_Qualitäten: 1b; Sicherheitsklasse: -
 | H2 Ebene 0 | WI-LB | 1113Wa 0812655406 | yes |  | m² | Trockenbauarbeiten | Wand | Innenwand 1-Schalig | WI-LB |  |  | 0 | 1113HWa0812655284 |  |  |  | 0 | AllplanAttributes - ash_W_Trockenbau_Qualitäten: 16; Sicherheitsklasse: -
 | H2 Ebene 0 | WI-HW 60 | 1113Wa 0813433176 | yes |  | m² | Zimmer- und Holzbauarbeiten | Wand | Innenwand 1-Schalig | WI-HW 60 |  |  | 0 | 1113HWa0812655284 |  |  |  | 0 |  |  | 0 | AllplanAttributes - Sicherheitsklasse: -
 | H2 Ebene 0 | Installationsraum | 1113Wa 0812438792 | yes |  | m² | Trockenbauarbeiten | Wand | Installationswand | Installationsraum |  |  | 0 | 1113HWa0812438779 | NEW |  |  | 0 |  |  | 0 | AllplanAttributes - Sicherheitsklasse: -
 | H2 Ebene 0 | WI-VS | 1113Wa 0812438794 | yes |  | m² | Trockenbauarbeiten | Wand | Installationswand | WI-VS |  |  | 0 | 1113HWa0812438779 | NEW |  |  | 0 |  |  | 0 | AllplanAttributes - W_Deckenanschluss: Gleitender Deckenanschluss Fall 01; ash_W_Trockenbau_Qualitäten: 18; Sicherheitsklasse: -
 | H2 Ebene 0 | WI-IW | 1113Wa 0812957541 | yes |  | m² | Trockenbauarbeiten | Wand | Installationswand | WI-IW |  |  | 0 | 1113HWa0812957539 | NEW |  |  | 0 |  |  | 0 | AllplanAttributes - W_Deckenanschluss: Gleitender Deckenanschluss Fall 01; ash_W_Trockenbau_Qualitäten: 18; Sicherheitsklasse: -
 | H2 Ebene 0 | WI-LB | 1113Wa 0813804637 | yes |  | m² | Trockenbauarbeiten | Wand | Innenwand 1-Schalig | WI-LB |  |  | 0 | 1113HWa0813804628 |  |  |  | 0 |  |  | 47 | AllplanAttributes - ash_W_Trockenbau_Qualitäten: 6; Sicherheitsklasse: -
 | H2 Ebene 0 | WI-HW 60 | 1113Wa 0813804642 | yes |  | m² | Zimmer- und Holzbauarbeiten | Wand | Innenwand 1-Schalig | WI-HW 60 |  |  | 0 | 1113HWa0813804628 |  |  |  | 0 |  |  | 47 | AllplanAttributes - Sicherheitsklasse: -
 | H2 Ebene 0 | WI-IW | 1113Wa 0812464590 | yes |  | m² | Trockenbauarbeiten | Wand | Installationswand | WI-IW |  |  | 0 | 1113HWa0812464589 | NEW |  |  | 0 |  |  | 0 | AllplanAttributes - W_Deckenanschluss: Gleitender Deckenanschluss Fall 01; ash_W_Trockenbau_Qualitäten: 18; Sicherheitsklasse: -
 | H2 Ebene 0 | Installationsraum | 1113Wa 0812464591 | yes |  | m² | Trockenbauarbeiten | Wand | Installationswand | Installationsraum |  |  | 0 | 1113HWa0812464589 | NEW |  |  | 0 |  |  | 0 | AllplanAttributes - Sicherheitsklasse: -
 | H2 Ebene 0 | WI-IW | 1113Wa 0812464676 | yes |  | m² | Trockenbauarbeiten | Wand | Installationswand | WI-IW |  |  | 0 | 1113HWa0812464675 | NEW |  |  | 0 |  |  | 0 | AllplanAttributes - W_Deckenanschluss: Gleitender Deckenanschluss Fall 01; ash_W_Trockenbau_Qualitäten: 18; Sicherheitsklasse: -
 | H2 Ebene 0 | WI-LB | 1113Wa 0812447359 | yes |  | m² | Trockenbauarbeiten | Wand | Innenwand 1-Schalig | WI-LB |  |  | 0 | 1113HWa0812430573 | OTHER |  |  | 0 | AllplanAttributes - ash_W_Trockenbau_Qualitäten: 9; Sicherheitsklasse: -
 | H2 Ebene 0 | WI-STB | 1113Wa 0814156792 | yes |  | m² | Zimmer- und Holzbauarbeiten | Wand | Innenwand 1-Schalig | WI-STB |  |  | 0 | 1113HWa0812430573 | NEW |  |  | 0 |  |  | - | AllplanAttributes - Sicherheitsklasse: -
 | H2 Ebene 0 | WI-HW 60 | 1113Wa 0814119137 | yes |  | m² | Zimmer- und Holzbauarbeiten | Wand | Innenwand 1-Schalig | WI-HW 60 |  |  | 0 | 1113HWa0814119077 |  |  |  | 0 |  |  | 47 | AllplanAttributes - Sicherheitsklasse: -
 | H2 Ebene 0 | WI-LB | 1113Wa 0814119142 |  |  | m² | Trockenbauarbeiten | Wand | Innenwand 1-Schalig | WI-LB |  |  | 0 | 1113HWa0814119077 |  |  |  | 0 |  |  | 47 | AllplanAttributes - ash_W_Trockenbau_Qualitäten: 6; Sicherheitsklasse: -
 | H2 Ebene 0 | WI-HW 60 | 1113Wa 0814180105 | yes |  | m² | Zimmer- und Holzbauarbeiten | Wand | Innenwand 1-Schalig | WI-HW 60 |  |  | 0 | 1113HWa0814180098 |  |  |  | 0 |  |  | 47 | AllplanAttributes - Sicherheitsklasse: -
 | H2 Ebene 0 | WI-LB | 1113Wa 0814180112 |  |  | m² | Trockenbauarbeiten | Wand | Innenwand 1-Schalig | WI-LB |  |  | 0 | 1113HWa0814180098 |  |  |  | 0 |  |  | 47 | AllplanAttributes - ash_W_Trockenbau_Qualitäten: 6; Sicherheitsklasse: -
 | H2 Ebene 0 | WI-HW 60 | 1113Wa 0814130784 | yes |  | m² | Zimmer- und Holzbauarbeiten | Wand | Innenwand 1-Schalig | WI-HW 60 |  |  | 0 | 1113HWa0814130776 | NEW | no |  | 0 |  |  | 47 | AllplanAttributes - Sicherheitsklasse: -
 | H2 Ebene 0 | WI-LB | 1113Wa 0814130788 | yes |  | m² | Trockenbauarbeiten | Wand | Innenwand 1-Schalig | WI-LB |  |  | 0 | 1113HWa0814130776 | NEW | no |  | 0 |  |  | 47 | AllplanAttributes - ash_W_Trockenbau_Qualitäten: 6; Sicherheitsklasse: -
 | H2 Ebene 0 | WI-HW 60 | 1113Wa 0812438228 | yes |  | m² | Zimmer- und Holzbauarbeiten | Wand | Innenwand 1-Schalig | WI-HW 60 |  |  | 0 | 1113HWa0812432924 | NEW | no |  | 0 |  |  | 47 | AllplanAttributes - Sicherheitsklasse: -
 | H2 Ebene 0 | WI-LB | 1113Wa 0813141038 | yes |  | m² | Trockenbauarbeiten | Wand | Innenwand 1-Schalig | WI-LB |  |  | 0 | 1113HWa0812432924 | NEW | no |  | 0 |  |  | 47 | AllplanAttributes - ash_W_Trockenbau_Qualitäten: 6; Sicherheitsklasse: -
 | H2 Ebene 0 | WI-HW 60 | 1113Wa 0814138083 | yes |  | m² | Zimmer- und Holzbauarbeiten | Wand | Innenwand 1-Schalig | WI-HW 60 |  |  | 0 | 1113HWa0814137866 | NEW | no |  | 0 |  |  | 47 | AllplanAttributes - Sicherheitsklasse: -
 | H2 Ebene 0 | WI-LB | 1113Wa 0814138081 | yes |  | m² | Trockenbauarbeiten | Wand | Innenwand 1-Schalig | WI-LB |  |  | 0 | 1113HWa0814137866 | NEW | no |  | 0 |  |  | 47 | AllplanAttributes - ash_W_Trockenbau_Qualitäten: 6; Sicherheitsklasse: -
 | H2 Ebene 0 | WI-IW | 1113Wa 0812534077 | yes |  | m² | Trockenbauarbeiten | Wand | Installationswand | WI-IW |  |  | 0 | 1113HWa0812534066 | NEW |  |  | 0 |  |  | 0 | AllplanAttributes - W_Deckenanschluss: Gleitender Deckenanschluss Fall 01; ash_W_Trockenbau_Qualitäten: 11; Sicherheitsklasse: -
 | H2 Ebene 0 | Installationsraum | 1113Wa 0812534075 | yes |  | m² | Trockenbauarbeiten | Wand | Installationswand | Installationsraum |  |  | 0 | 1113HWa0812534066 | NEW |  |  | 0 |  |  | 0 | AllplanAttributes - Sicherheitsklasse: -
 | H2 Ebene 0 | WI-IW | 1113Wa 0812534079 | yes |  | m² | Trockenbauarbeiten | Wand | Installationswand | WI-IW |  |  | 0 | 1113HWa0812534066 | NEW |  |  | 0 |  |  | 0 | AllplanAttributes - W_Deckenanschluss: Gleitender Deckenanschluss Fall 01; ash_W_Trockenbau_Qualitäten: 11; Sicherheitsklasse: -
 | H2 Ebene 0 | Installationsraum | 1113Wa 0812816616 | yes |  | m² | Trockenbauarbeiten | Wand | Installationswand | Installationsraum |  |  | 0 | 1113HWa0812816615 | NEW |  |  | 0 |  |  | 0 | AllplanAttributes - Sicherheitsklasse: -
 | H2 Ebene 0 | WI-IW | 1113Wa 0812816617 | yes |  | m² | Trockenbauarbeiten | Wand | Installationswand | WI-IW |  |  | 0 | 1113HWa0812816615 | NEW |  |  | 0 |  |  | 0 | AllplanAttributes - W_Deckenanschluss: Gleitender Deckenanschluss Fall 01; ash_W_Trockenbau_Qualitäten: 2; Sicherheitsklasse: -
 | H2 Ebene 0 | Installationsraum | 1113Wa 0812437629 | yes |  | m² | Trockenbauarbeiten | Wand | Installationswand | Installationsraum |  |  | 0 | 1113HWa0812430732 | NEW |  |  | 0 |  |  | 0 | AllplanAttributes - Sicherheitsklasse: -
 | H2 Ebene 0 | WI-VS | 1113Wa 0812437623 | yes |  | m² | Trockenbauarbeiten | Wand | Installationswand | WI-VS |  |  | 0 | 1113HWa0812430732 | NEW |  |  | 0 |  |  | 0 | AllplanAttributes - W_Deckenanschluss: Gleitender Deckenanschluss Fall 01; ash_W_Trockenbau_Qualitäten: 2; Sicherheitsklasse: -
 | H2 Ebene 0 | WI-LB | 1113Wa 0814181610 | yes |  | m² | Trockenbauarbeiten | Wand | Innenwand 1-Schalig | WI-LB |  |  | 0 | 1113HWa0814181609 | NEW |  |  | 0 |  |  | 47 | AllplanAttributes - W_Deckenanschluss: Gleitender Deckenanschluss Fall 01; ash_W_Trockenbau_Qualitäten: 1b; Sicherheitsklasse: -
 | H2 Ebene 0 | WI-LB | 1113Wa 0814181631 | yes |  | m² | Trockenbauarbeiten | Wand | Innenwand 1-Schalig | WI-LB |  |  | 0 | 1113HWa0814181630 | NEW |  |  | 0 |  |  | 47 | AllplanAttributes - W_Deckenanschluss: Gleitender Deckenanschluss Fall 01; ash_W_Trockenbau_Qualitäten: 1b; Sicherheitsklasse: -
 | H2 Ebene 0 | WI-LB | 1113Wa 0814161138 | yes |  | m² | Trockenbauarbeiten | Wand | Innenwand 1-Schalig | WI-LB |  |  | 0 | 1113HWa0814161137 | NEW |  |  | 0 |  |  | 47 | AllplanAttributes - W_Deckenanschluss: Gleitender Deckenanschluss Fall 01; Sicherheitsklasse: -
 | H2 Ebene 0 | WI-LB | 1113Wa 0814181743 | yes |  | m² | Trockenbauarbeiten | Wand | Innenwand 1-Schalig | WI-LB |  |  | 0 | 1113HWa0814181742 | NEW |  |  | 0 |  |  | 47 | AllplanAttributes - W_Deckenanschluss: Gleitender Deckenanschluss Fall 01; ash_W_Trockenbau_Qualitäten: 1b; Sicherheitsklasse: -
 | H2 Ebene 0 | WI-LB | 1113Wa 0814181764 | yes |  | m² | Trockenbauarbeiten | Wand | Innenwand 1-Schalig | WI-LB |  |  | 0 | 1113HWa0814181763 | NEW |  |  | 0 |  |  | 47 | AllplanAttributes - W_Deckenanschluss: Gleitender Deckenanschluss Fall 01; ash_W_Trockenbau_Qualitäten: 1b; Sicherheitsklasse: -
 | H2 Ebene 0 | WI-IW | 1113Wa 0814182242 | yes |  | m² | Trockenbauarbeiten | Wand | Installationswand | WI-IW |  |  | 0 | 1113HWa0814182241 | NEW | no |  | 0 |  |  | 47 | AllplanAttributes - W_Deckenanschluss: Gleitender Deckenanschluss Fall 01; ash_W_Trockenbau_Qualitäten: 18; Sicherheitsklasse: -
 | H2 Ebene 0 | WI-IW | 1113Wa 0814182252 | yes |  | m² | Trockenbauarbeiten | Wand | Installationswand | WI-IW |  |  | 0 | 1113HWa0814182251 | NEW | no |  | 0 |  |  | 47 | AllplanAttributes - W_Deckenanschluss: Gleitender Deckenanschluss Fall 01; ash_W_Trockenbau_Qualitäten: 18; Sicherheitsklasse: -
 | H2 Ebene 0 | WI-LB | 1113Wa 0814027803 | yes |  | m² | Trockenbauarbeiten | Wand | Innenwand 1-Schalig | WI-LB |  |  | 0 | 1113HWa0814027802 | NEW |  |  | 0 |  |  | 47 | AllplanAttributes - W_Deckenanschluss: Gleitender Deckenanschluss Fall 01; ash_W_Trockenbau_Qualitäten: 1a; Sicherheitsklasse: -
 | H2 Ebene 0 | WI-RIR | 1113Wa 0814006150 | yes |  | m² | Tischlerarbeiten | Wand | Innenwand 1-Schalig | WI-RIR |  |  | 0 | 1113HWa0814006149 | NEW |  |  | 0 |  |  | 47 | AllplanAttributes - W_Deckenanschluss: Gleitender Deckenanschluss Fall 01; ash_W_Trockenbau_Qualitäten: 1b
 | H2 Ebene 0 | WI-LB | 1113Wa 0814182742 | yes |  | m² | Trockenbauarbeiten | Wand | Innenwand 1-Schalig | WI-LB |  |  | 0 | 1113HWa0814182741 | NEW | no |  | 0 |  |  | 47 | AllplanAttributes - W_Deckenanschluss: Gleitender Deckenanschluss Fall 01; ash_W_Trockenbau_Qualitäten: 1d
 | H2 Ebene 0 | WI-LB | 1113Wa 0812447098 | yes |  | m² | Trockenbauarbeiten | Wand | Innenwand 1-Schalig | WI-LB |  |  | 0 | 1113HWa0812434685 |  |  |  | 0 |  |  | 52 | AllplanAttributes - Ortscode_Geschoßbezeichnung: E00; W_Deckenanschluss: Gleitender Deckenanschluss Fall 01; ash_W_Trockenbau_Qualitäten: 4; Sicherheitsklasse: -
WV 1.1 | H2 Ebene 0 |  | 1113Sma0814160264 |  | VUK1 - Hängeschrank | St | Trockenbauarbeiten | SmartPart | WV 1.1 |  |  |  | 0.2 |  |  |  |  | - | AllplanAttributes - ash_W_Trockenbau_Qualitäten: 18; Text1: WA2012; UK: 0 m; OK: 0 m; V6: 0 m; V7: 0 m; V8: 0 m; V9: 0; Länge: 2.45 m; Dicke: 0.025 m; Höhe: 0.2 m; Programmversion: 3.1; Text3: 0; Plugin_Bezeichnung: MainObject; Plugin_Objektname: SmartPartCompressed; Version: 1.1; Abstand_Öffn_Unten: 2.35 m; ash T_Feuchtebeständigkeit: nein; Feuerwiderstandsklasse~: nein
 | H2 Ebene 0 | WI-LB | 1113Wa 0812468455 |  |  | m² | Trockenbauarbeiten | Wand |  |  |  |  | 0 | 1113HWa0812468442 |  |  |  | 0 |  |  | 0 | AllplanAttributes - Ortscode_Geschoßbezeichnung: E00; W_Deckenanschluss: Gleitender Deckenanschluss Fall 03; ash_W_Trockenbau_Qualitäten: 10a; Sicherheitsklasse: -
 | H2 Ebene 0 | Installationsraum | 1113Wa 0812838161 | yes |  | m² | Trockenbauarbeiten | Wand | Installationswand | Installationsraum |  |  | 0 | 1113HWa0812838160 | NEW |  |  | 0 |  |  | 0 | AllplanAttributes - Sicherheitsklasse: -
 | H2 Ebene 0 | WI-VS | 1113Wa 0812838162 | yes |  | m² | Trockenbauarbeiten | Wand | Installationswand | WI-VS |  |  | 0 | 1113HWa0812838160 | NEW |  |  | 0 |  |  | 0 | AllplanAttributes - W_Deckenanschluss: Gleitender Deckenanschluss Fall 03; ash_W_Trockenbau_Qualitäten: 21; Sicherheitsklasse: -
 | H2 Ebene 0 | WI-LB | 1113Wa 0812468458 |  |  | m² | Trockenbauarbeiten | Wand |  |  |  |  | 0 | 1113HWa0812468444 |  |  |  | 0 |  |  | 0 | AllplanAttributes - Ortscode_Geschoßbezeichnung: E00; W_Deckenanschluss: Gleitender Deckenanschluss Fall 03; ash_W_Trockenbau_Qualitäten: 10a; Sicherheitsklasse: -
WV 1.1 | H2 Ebene 0 |  | 1113Sma0814160789 |  | VUK1 - Feuerlöscher | St | Trockenbauarbeiten | SmartPart | WV 1.1 |  |  |  | 0.2 |  |  |  |  | - | AllplanAttributes - Text1: WA; UK: 0 m; OK: 0 m; V6: 0 m; V7: 0 m; V8: 0 m; V9: 0; Länge: 0.3 m; Dicke: 0.025 m; Höhe: 0.7 m; Programmversion: 3.1; Text3: 0; Plugin_Bezeichnung: MainObject; Plugin_Objektname: SmartPartCompressed; Version: 1.1; Abstand_Öffn_Unten: 0.85 m; ash T_Feuchtebeständigkeit: nein; Feuerwiderstandsklasse~: nein
 | H2 Ebene 0 | Installationsraum | 1113Wa 0812442539 | yes |  | m² | Trockenbauarbeiten | Wand | Installationswand | Installationsraum |  |  | 0 | 1113HWa0812425591 | NEW |  |  | 0 |  |  | 0 | AllplanAttributes - Sicherheitsklasse: -
 | H2 Ebene 0 | WI-VS | 1113Wa 0812442545 | yes |  | m² | Trockenbauarbeiten | Wand | Installationswand | WI-VS |  |  | 0 | 1113HWa0812425591 | NEW |  |  | 0 |  |  | 0 | AllplanAttributes - W_Deckenanschluss: Gleitender Deckenanschluss Fall 01; ash_W_Trockenbau_Qualitäten: 18; Sicherheitsklasse: -
 | H2 Ebene 0 | WI-LB | 1113Wa 0814190236 | yes |  | m² | Trockenbauarbeiten | Wand | Innenwand 1-Schalig | WI-LB |  |  | 0 | 1113HWa0814190235 | NEW |  |  | 0 | AllplanAttributes - W_Deckenanschluss: Gleitender Deckenanschluss Fall 01; ash_W_Trockenbau_Qualitäten: 18; Sicherheitsklasse: -
 | H2 Ebene 0 | WI-LB | 1113Wa 0814190259 | yes |  | m² | Trockenbauarbeiten | Wand | Innenwand 1-Schalig | WI-LB |  |  | 0 | 1113HWa0814190258 | NEW |  |  | 0 | AllplanAttributes - W_Deckenanschluss: Gleitender Deckenanschluss Fall 01; ash_W_Trockenbau_Qualitäten: 18; Sicherheitsklasse: -
 | H2 Ebene 0 | WI-LB | 1113Wa 0814190278 | yes |  | m² | Trockenbauarbeiten | Wand | Innenwand 1-Schalig | WI-LB |  |  | 0 | 1113HWa0814190277 | NEW |  |  | 0 | AllplanAttributes - W_Deckenanschluss: Gleitender Deckenanschluss Fall 01; ash_W_Trockenbau_Qualitäten: 18; Sicherheitsklasse: -
 | H2 Ebene 0 | WI-LB | 1113Wa 0814190289 | yes |  | m² | Trockenbauarbeiten | Wand | Innenwand 1-Schalig | WI-LB |  |  | 0 | 1113HWa0814190288 | NEW |  |  | 0 | AllplanAttributes - W_Deckenanschluss: Gleitender Deckenanschluss Fall 01; ash_W_Trockenbau_Qualitäten: 18; Sicherheitsklasse: -
 | H2 Ebene 0 | WI-LB | 1113Wa 0814190300 | yes |  | m² | Trockenbauarbeiten | Wand | Innenwand 1-Schalig | WI-LB |  |  | 0 | 1113HWa0814190299 | NEW |  |  | 0 | AllplanAttributes - W_Deckenanschluss: Gleitender Deckenanschluss Fall 01; ash_W_Trockenbau_Qualitäten: 18; Sicherheitsklasse: -
 | H2 Ebene 0 | WI-LB | 1113Wa 0814190314 | yes |  | m² | Trockenbauarbeiten | Wand | Innenwand 1-Schalig | WI-LB |  |  | 0 | 1113HWa0814190313 | NEW |  |  | 0 | AllplanAttributes - W_Deckenanschluss: Gleitender Deckenanschluss Fall 01; ash_W_Trockenbau_Qualitäten: 18; Sicherheitsklasse: -
 | H2 Ebene 0 | WI-LB | 1113Wa 0814190335 | yes |  | m² | Trockenbauarbeiten | Wand | Innenwand 1-Schalig | WI-LB |  |  | 0 | 1113HWa0814190334 | NEW |  |  | 0 | AllplanAttributes - W_Deckenanschluss: Gleitender Deckenanschluss Fall 01; ash_W_Trockenbau_Qualitäten: 18; Sicherheitsklasse: -
 | H2 Ebene 0 | WI-LB | 1113Wa 0814190346 | yes |  | m² | Trockenbauarbeiten | Wand | Innenwand 1-Schalig | WI-LB |  |  | 0 | 1113HWa0814190345 | NEW |  |  | 0 | AllplanAttributes - W_Deckenanschluss: Gleitender Deckenanschluss Fall 01; ash_W_Trockenbau_Qualitäten: 18; Sicherheitsklasse: -
 | H2 Ebene 0 | WI-LB | 1113Wa 0813939255 | yes | Codetext | m² | Trockenbauarbeiten | Wand | Innenwand 1-Schalig | WI-LB | 0 | A | 3.75 | 1113HWa0813939229 | NEW | no | no | 0 | 0 | no | 0 | no | Codetext | AllplanAttributes - W_Deckenanschluss: Gleitender Deckenanschluss Fall 01; Positionsnummer_Text: U100
 | H2 Ebene 0 | WI-LB | 1113Wa 0813939286 | yes | Codetext | m² | Trockenbauarbeiten | Wand | Innenwand 1-Schalig | WI-LB | 0 | A | 3.75 | 1113HWa0813939262 | NEW | no | no | 0 | 0 | no | 0 | no | Codetext | AllplanAttributes - W_Deckenanschluss: Gleitender Deckenanschluss Fall 01; Positionsnummer_Text: U100
 | H2 Ebene 0 | WI-LB | 1113Wa 0812447073 |  |  | m² | Trockenbauarbeiten | Wand | Innenwand 1-Schalig | WI-LB |  |  | 0 | 1113HWa0812434671 |  |  |  | 0 |  |  | 52 | AllplanAttributes - Ortscode_Geschoßbezeichnung: E00; W_Deckenanschluss: Gleitender Deckenanschluss Fall 01; ash_W_Trockenbau_Qualitäten: 4; Sicherheitsklasse: -
 | H2 Ebene 0 | WI-LB | 1113Wa 0812447076 |  |  | m² | Trockenbauarbeiten | Wand | Innenwand 1-Schalig | WI-LB |  |  | 0 | 1113HWa0812434677 |  |  |  | 0 |  |  | 0 | AllplanAttributes - ash_W_Trockenbau_Qualitäten: 6; Sicherheitsklasse: -
 | H2 Ebene 0 | WI-HW 60 | 1113Wa 0813138117 |  |  | m² | Zimmer- und Holzbauarbeiten | Wand | Innenwand 1-Schalig | WI-HW 60 |  |  | 0 | 1113HWa0812434677 |  |  |  | 0 |  |  | 52 | AllplanAttributes - Sicherheitsklasse: -
 | H2 Ebene 0 | WI-LB | 1113Wa 0812440015 | yes |  | m² | Trockenbauarbeiten | Wand | Innenwand 1-Schalig | WI-LB |  |  | 0 | 1113HWa0812437912 | NEW |  |  | 0 | AllplanAttributes - ash_W_Trockenbau_Qualitäten: 6; Sicherheitsklasse: -
 | H2 Ebene 0 | WI-HW 60 | 1113Wa 0813443016 | yes |  | m² | Zimmer- und Holzbauarbeiten | Wand | Innenwand 1-Schalig | WI-HW 60 |  |  | 0 | 1113HWa0812437912 | NEW |  |  | 0 |  |  | 47 | AllplanAttributes - Sicherheitsklasse: -
 | H2 Ebene 0 | WI-LB | 1113Wa 0814113433 | yes |  | m² | Trockenbauarbeiten | Wand | Innenwand 1-Schalig | WI-LB |  |  | 0 | 1113HWa0814113432 | NEW |  |  |  |  |  | 47 | AllplanAttributes - W_Deckenanschluss: Gleitender Deckenanschluss Fall 01; ash_W_Trockenbau_Qualitäten: 8
 | H2 Ebene 0 | WI-LB | 1113Wa 0812437916 |  |  | m² | Trockenbauarbeiten | Wand | Innenwand 1-Schalig | WI-LB |  |  | 0 | 1113HWa0812434662 | OTHER |  |  | 0 | AllplanAttributes - ash_W_Trockenbau_Qualitäten: 15; Sicherheitsklasse: -
 | H2 Ebene 0 | WI-HW 60 | 1113Wa 0813138800 | yes |  | m² | Zimmer- und Holzbauarbeiten | Wand | Innenwand 1-Schalig | WI-HW 60 |  |  | 0 | 1113HWa0812434662 | NEW |  |  | 0 |  |  | 47 | AllplanAttributes - Sicherheitsklasse: -
 | H2 Ebene 0 | Installationsraum | 1113Wa 0813443268 | yes |  | m² | Trockenbauarbeiten | Wand | Innenwand 1-Schalig | Installationsraum |  |  | 0 | 1113HWa0812434662 | NEW |  |  | 0 |  |  | 0 | AllplanAttributes - Sicherheitsklasse: -
 | H2 Ebene 0 | WI-LB | 1113Wa 0814114381 |  |  | m² | Trockenbauarbeiten | Wand | Innenwand 1-Schalig | WI-LB |  |  | 0 | 1113HWa0812434662 | OTHER |  |  | 0 |  |  | 47 | AllplanAttributes - ash_W_Trockenbau_Qualitäten: 15; Sicherheitsklasse: -
 | H2 Ebene 0 | WI-STB | 1113Wa 0814197367 | yes |  | m² | Zimmer- und Holzbauarbeiten | Wand | Innenwand 1-Schalig | WI-STB |  |  | 0 | 1113HWa0814197361 | NEW |  |  | 0 |  |  | 0 | AllplanAttributes - Sicherheitsklasse: -
 | H2 Ebene 0 | WI-LB | 1113Wa 0814197369 |  |  | m² | Trockenbauarbeiten | Wand | Innenwand 1-Schalig | WI-LB |  |  | 0 | 1113HWa0814197361 | OTHER |  |  | 0 | AllplanAttributes - ash_W_Trockenbau_Qualitäten: 9; Sicherheitsklasse: -
 | H2 Ebene 0 | WI-LB | 1113Wa 0812441870 |  |  | m² | Trockenbauarbeiten | Wand |  |  |  |  | 0 | 1113HWa0812441736 |  |  |  | 0 |  |  | 0 | AllplanAttributes - Ortscode_Geschoßbezeichnung: E00; W_Deckenanschluss: Gleitender Deckenanschluss Fall 03; ash_W_Trockenbau_Qualitäten: 10a; Sicherheitsklasse: -
 | H2 Ebene 0 | WI-LB | 1113Wa 0814114138 | yes |  | m² | Trockenbauarbeiten | Wand | Innenwand 1-Schalig | WI-LB |  |  | 0 | 1113HWa0814114137 | NEW |  |  |  |  |  | 47 | AllplanAttributes - W_Deckenanschluss: Gleitender Deckenanschluss Fall 01; ash_W_Trockenbau_Qualitäten: 1a
 | H2 Ebene 0 | WI-LB | 1113Wa 0814114181 | yes |  | m² | Trockenbauarbeiten | Wand | Innenwand 1-Schalig | WI-LB |  |  | 0 | 1113HWa0814114180 | NEW | no |  |  |  |  | 47 | AllplanAttributes - W_Deckenanschluss: Gleitender Deckenanschluss Fall 01; ash_W_Trockenbau_Qualitäten: 8
 | H2 Ebene 0 | WI-LB | 1113Wa 0814206452 | yes |  | m² | Trockenbauarbeiten | Wand | Innenwand 1-Schalig | WI-LB |  |  | 0 | 1113HWa0814206451 | NEW |  |  | 0 |  |  | 0 | AllplanAttributes - ash_W_Trockenbau_Qualitäten: 6; Sicherheitsklasse: -
 | H2 Ebene 0 | WI-LB | 1113Wa 0814206500 | yes |  | m² | Trockenbauarbeiten | Wand | Innenwand 1-Schalig | WI-LB |  |  | 0 | 1113HWa0814206499 | NEW |  |  | 0 |  |  | 0 | AllplanAttributes - ash_W_Trockenbau_Qualitäten: 6; Sicherheitsklasse: -
WV 1.1 | H2 Ebene 0 |  | 1113Sma0814160747 |  | VUK1 - Feuerlöscher | St | Trockenbauarbeiten | SmartPart | WV 1.1 |  |  |  | 0.2 |  |  |  |  | - | AllplanAttributes - Text1: WA; UK: 0 m; OK: 0 m; V6: 0 m; V7: 0 m; V8: 0 m; V9: 0; Länge: 0.3 m; Dicke: 0.025 m; Höhe: 0.7 m; Programmversion: 3.1; Text3: 0; Plugin_Bezeichnung: MainObject; Plugin_Objektname: SmartPartCompressed; Version: 1.1; Abstand_Öffn_Unten: 0.85 m; ash T_Feuchtebeständigkeit: nein; Feuerwiderstandsklasse~: nein
 | H2 Ebene 0 | WI-LB | 1113Wa 0814206629 | yes |  | m² | Trockenbauarbeiten | Wand | Innenwand 1-Schalig | WI-LB |  |  | 0 | 1113HWa0814206628 | NEW | no |  | 0 | AllplanAttributes - W_Deckenanschluss: Gleitender Deckenanschluss Fall 01; ash_W_Trockenbau_Qualitäten: 18; Sicherheitsklasse: -
 | H2 Ebene 0 | WI-LB | 1113Wa 0814206463 | yes |  | m² | Trockenbauarbeiten | Wand | Innenwand 1-Schalig | WI-LB |  |  | 0 | 1113HWa0814206462 | NEW |  |  | 0 |  |  | 0 | AllplanAttributes - ash_W_Trockenbau_Qualitäten: 6; Sicherheitsklasse: -
 | H2 Ebene 0 | WI-LB | 1113Wa 0814206661 | yes |  | m² | Trockenbauarbeiten | Wand | Innenwand 1-Schalig | WI-LB |  |  | 0 | 1113HWa0814206660 | NEW |  |  | 0 |  |  | 0 | AllplanAttributes - ash_W_Trockenbau_Qualitäten: 6; Sicherheitsklasse: -
 | H2 Ebene 0 | WI-LB | 1113Wa 0814206909 | yes |  | m² | Trockenbauarbeiten | Wand | Innenwand 1-Schalig | WI-LB |  |  | 0 | 1113HWa0814206908 | NEW | no |  | 0 | AllplanAttributes - W_Deckenanschluss: Gleitender Deckenanschluss Fall 01; ash_W_Trockenbau_Qualitäten: 18; Sicherheitsklasse: -
 | H2 Ebene 0 | WI-LB | 1113Wa 0814206348 | yes |  | m² | Trockenbauarbeiten | Wand | Innenwand 1-Schalig | WI-LB |  |  | 0 | 1113HWa0814206347 | NEW | no |  | 0 | AllplanAttributes - W_Deckenanschluss: Gleitender Deckenanschluss Fall 01; ash_W_Trockenbau_Qualitäten: 18; Sicherheitsklasse: -
 | H2 Ebene 0 | WI-LB | 1113Wa 0814206695 | yes |  | m² | Trockenbauarbeiten | Wand | Innenwand 1-Schalig | WI-LB |  |  | 0 | 1113HWa0814206694 | NEW | no |  | 0 | AllplanAttributes - W_Deckenanschluss: Gleitender Deckenanschluss Fall 01; ash_W_Trockenbau_Qualitäten: 18; Sicherheitsklasse: -
 | H2 Ebene 0 | WI-LB | 1113Wa 0814207071 | yes |  | m² | Trockenbauarbeiten | Wand | Innenwand 1-Schalig | WI-LB |  |  | 0 | 1113HWa0814207065 | NEW |  |  | 0 |  |  | 0 | AllplanAttributes - ash_W_Trockenbau_Qualitäten: 6; Sicherheitsklasse: -
 | H2 Ebene 0 | WI-LB | 1113Wa 0814207104 | yes |  | m² | Trockenbauarbeiten | Wand | Innenwand 1-Schalig | WI-LB |  |  | 0 | 1113HWa0814207075 | NEW | no |  | 0 | AllplanAttributes - W_Deckenanschluss: Gleitender Deckenanschluss Fall 01; ash_W_Trockenbau_Qualitäten: 18; Sicherheitsklasse: -
 | H2 Ebene 0 | WI-LB | 1113Wa 0814207084 | yes |  | m² | Trockenbauarbeiten | Wand | Innenwand 1-Schalig | WI-LB |  |  | 0 | 1113HWa0814207076 | NEW |  |  | 0 |  |  | 0 | AllplanAttributes - ash_W_Trockenbau_Qualitäten: 6; Sicherheitsklasse: -
 | H2 Ebene 0 | WI-LB | 1113Wa 0814207082 | yes |  | m² | Trockenbauarbeiten | Wand | Innenwand 1-Schalig | WI-LB |  |  | 0 | 1113HWa0814207077 | NEW |  |  | 0 |  |  | 0 | AllplanAttributes - ash_W_Trockenbau_Qualitäten: 6; Sicherheitsklasse: -
 | H2 Ebene 0 | WI-LB | 1113Wa 0814207116 | yes |  | m² | Trockenbauarbeiten | Wand | Innenwand 1-Schalig | WI-LB |  |  | 0 | 1113HWa0814207087 | NEW | no |  | 0 | AllplanAttributes - W_Deckenanschluss: Gleitender Deckenanschluss Fall 01; ash_W_Trockenbau_Qualitäten: 18; Sicherheitsklasse: -
 | H2 Ebene 0 | WI-LB | 1113Wa 0814207100 | yes |  | m² | Trockenbauarbeiten | Wand | Innenwand 1-Schalig | WI-LB |  |  | 0 | 1113HWa0814207089 | NEW | no |  | 0 | AllplanAttributes - W_Deckenanschluss: Gleitender Deckenanschluss Fall 01; ash_W_Trockenbau_Qualitäten: 18; Sicherheitsklasse: -
 | H2 Ebene 0 | WI-LB | 1113Wa 0814207121 | yes |  | m² | Trockenbauarbeiten | Wand | Innenwand 1-Schalig | WI-LB |  |  | 0 | 1113HWa0814207090 | NEW | no |  | 0 | AllplanAttributes - W_Deckenanschluss: Gleitender Deckenanschluss Fall 01; ash_W_Trockenbau_Qualitäten: 18; Sicherheitsklasse: -
 | H2 Ebene 0 | WI-LB | 1113Wa 0814207118 | yes |  | m² | Trockenbauarbeiten | Wand | Innenwand 1-Schalig | WI-LB |  |  | 0 | 1113HWa0814207105 | NEW |  |  | 0 | AllplanAttributes - W_Deckenanschluss: Gleitender Deckenanschluss Fall 01; ash_W_Trockenbau_Qualitäten: 1a; Sicherheitsklasse: -
WV 1.1 | H2 Ebene 0 |  | 1113Sma0814160803 |  | VUK1 - Feuerlöscher | St | Trockenbauarbeiten | SmartPart | WV 1.1 |  |  |  | 0.2 |  |  |  |  | - | AllplanAttributes - Text1: WA; UK: 0 m; OK: 0 m; V6: 0 m; V7: 0 m; V8: 0 m; V9: 0; Länge: 0.3 m; Dicke: 0.025 m; Höhe: 0.7 m; Programmversion: 3.1; Text3: 0; Plugin_Bezeichnung: MainObject; Plugin_Objektname: SmartPartCompressed; Version: 1.1; Abstand_Öffn_Unten: 0.85 m; ash T_Feuchtebeständigkeit: nein; Feuerwiderstandsklasse~: nein
 | H2 Ebene 0 | WI-LB | 1113Wa 0814207288 | yes |  | m² | Trockenbauarbeiten | Wand | Innenwand 1-Schalig | WI-LB |  |  | 0 | 1113HWa0814207287 | NEW |  |  | 0 |  |  | 0 | AllplanAttributes - ash_W_Trockenbau_Qualitäten: 6; Sicherheitsklasse: -
 | H2 Ebene 0 | WI-LB | 1113Wa 0814207299 | yes |  | m² | Trockenbauarbeiten | Wand | Innenwand 1-Schalig | WI-LB |  |  | 0 | 1113HWa0814207298 | NEW |  |  | 0 |  |  | 0 | AllplanAttributes - ash_W_Trockenbau_Qualitäten: 6; Sicherheitsklasse: -
 | H2 Ebene 0 | WI-LB | 1113Wa 0813344976 | yes |  | m² | Trockenbauarbeiten | Wand | Innenwand 1-Schalig | WI-LB |  |  | 0 | 1113HWa0813344573 | NEW |  |  | 0 |  |  | 0 | AllplanAttributes - W_Deckenanschluss: Gleitender Deckenanschluss Fall 01; ash_W_Trockenbau_Qualitäten: 12b; Sicherheitsklasse: -
 | H2 Ebene 0 | WI-LW 60 | 1113Wa 0813243858 | yes |  | m² | Trockenbauarbeiten | Wand | Innenwand 1-Schalig | WI-LW 60 |  |  | 0 | 1113HWa0813243845 | NEW |  |  | 0 |  |  | 0 | AllplanAttributes - W_Deckenanschluss: Gleitender Deckenanschluss Fall 01; ash_W_Trockenbau_Qualitäten: 12b; Sicherheitsklasse: -
 | H2 Ebene 0 | WI-LB | 1113Wa 0812440861 | yes |  | m² | Trockenbauarbeiten | Wand | Innenwand 1-Schalig | WI-LB |  |  | 0 | 1113HWa0812434689 | NEW |  |  | 0 |  |  | 0 | AllplanAttributes - W_Deckenanschluss: Gleitender Deckenanschluss Fall 01; ash_W_Trockenbau_Qualitäten: 12a; Sicherheitsklasse: -
 | H2 Ebene 0 | WI-HW 60 | 1113Wa 0812442493 | yes |  | m² | Zimmer- und Holzbauarbeiten | Wand | Innenwand 1-Schalig | WI-HW 60 |  |  | 0 | 1113HWa0812440566 | NEW |  |  | 0 |  |  | 47 | AllplanAttributes - Sicherheitsklasse: -
 | H2 Ebene 0 | WI-HW 60 | 1113Wa 0812441727 | yes |  | m² | Zimmer- und Holzbauarbeiten | Wand | Innenwand 1-Schalig | WI-HW 60 |  |  | 0 | 1113HWa0812440544 |  |  |  | 0 |  |  | 47 | AllplanAttributes - Sicherheitsklasse: -
 | H2 Ebene 0 | WI-LB | 1113Wa 0813136637 |  |  | m² | Trockenbauarbeiten | Wand | Innenwand 1-Schalig | WI-LB |  |  | 0 | 1113HWa0812440544 |  |  |  | 0 |  |  | 47 | AllplanAttributes - ash_W_Trockenbau_Qualitäten: 6; Sicherheitsklasse: -
 | H2 Ebene 0 | WI-LW 60 | 1113Wa 0812508669 | yes |  | m² | Trockenbauarbeiten | Wand | Innenwand 1-Schalig | WI-LW 60 |  |  | 0 | 1113HWa0812508668 | NEW |  |  | 0 |  |  | 0 | AllplanAttributes - W_Deckenanschluss: Gleitender Deckenanschluss Fall 01; ash_W_Trockenbau_Qualitäten: 12b; Sicherheitsklasse: -
 | H2 Ebene 0 | WI-LB | 1113Wa 0812440268 | yes |  | m² | Trockenbauarbeiten | Wand | Innenwand 1-Schalig | WI-LB |  |  | 0 | 1113HWa0812438825 | NEW |  |  | 0 |  |  | 0 | AllplanAttributes - W_Deckenanschluss: Gleitender Deckenanschluss Fall 01; ash_W_Trockenbau_Qualitäten: 12b; Sicherheitsklasse: -
 | H2 Ebene 0 | WI-HW 60 | 1113Wa 0812440265 | yes |  | m² | Zimmer- und Holzbauarbeiten | Wand | Innenwand 1-Schalig | WI-HW 60 |  |  | 0 | 1113HWa0812438820 | NEW |  |  | 0 |  |  | 47 | AllplanAttributes - Sicherheitsklasse: -
 | H2 Ebene 0 | WI-HW 60 | 1113Wa 0814140000 |  |  | m² | Zimmer- und Holzbauarbeiten | Wand | Innenwand 1-Schalig | WI-HW 60 |  |  | 0 | 1113HWa0814139626 |  |  |  | 0 |  |  | 47 | AllplanAttributes - Sicherheitsklasse: -
 | H2 Ebene 0 | WI-LB | 1113Wa 0814140005 |  |  | m² | Trockenbauarbeiten | Wand | Innenwand 1-Schalig | WI-LB |  |  | 0 | 1113HWa0814139626 |  |  |  | 0 |  |  | 47 | AllplanAttributes - ash_W_Trockenbau_Qualitäten: 6; Sicherheitsklasse: -
 | H2 Ebene 0 | WI-LB | 1113Wa 0812437372 | yes |  | m² | Trockenbauarbeiten | Wand | Innenwand 1-Schalig | WI-LB |  |  | 0 | 1113HWa0812425463 | NEW |  |  | 0 |  |  | 0 | AllplanAttributes - W_Deckenanschluss: Gleitender Deckenanschluss Fall 01; ash_W_Trockenbau_Qualitäten: 12b; Sicherheitsklasse: -
 | H2 Ebene 0 | Installationsraum | 1113Wa 0812437235 |  |  | m² | Trockenbauarbeiten | Wand |  |  |  |  | 0 | 1113HWa0812425828 |  |  |  | 0 |  |  | 0 | AllplanAttributes - Ortscode_Geschoßbezeichnung: E00; Sicherheitsklasse: -
 | H2 Ebene 0 | WI-VS | 1113Wa 0812437241 |  |  | m² | Trockenbauarbeiten | Wand |  |  |  |  | 0 | 1113HWa0812425828 |  |  |  | 0 |  |  | 0 | AllplanAttributes - Ortscode_Geschoßbezeichnung: E00; W_Deckenanschluss: Gleitender Deckenanschluss Fall 01; ash_W_Trockenbau_Qualitäten: 2; Sicherheitsklasse: -
 | H2 Ebene 0 | Installationsraum | 1113Wa 0812443686 |  |  | m² | Trockenbauarbeiten | Wand |  |  |  |  | 0 | 1113HWa0812425821 |  |  |  | 0 |  |  | 0 | AllplanAttributes - Ortscode_Geschoßbezeichnung: E00; Sicherheitsklasse: -
 | H2 Ebene 0 | WI-VS | 1113Wa 0812443616 |  |  | m² | Trockenbauarbeiten | Wand |  |  |  |  | 0 | 1113HWa0812425821 |  |  |  | 0 |  |  | 0 | AllplanAttributes - Ortscode_Geschoßbezeichnung: E00; W_Deckenanschluss: Gleitender Deckenanschluss Fall 01; ash_W_Trockenbau_Qualitäten: 2; Sicherheitsklasse: -
 | H2 Ebene 0 | WI-IW | 1113Wa 0813946795 | yes |  | m² | Trockenbauarbeiten | Wand | Installationswand | WI-IW |  |  | 0 | 1113HWa0813946794 |  |  |  | 0 |  |  | 0 | AllplanAttributes - W_Deckenanschluss: Gleitender Deckenanschluss Fall 01; ash_W_Trockenbau_Qualitäten: 11; Sicherheitsklasse: -
 | H2 Ebene 0 | Installationsraum | 1113Wa 0813946796 | yes |  | m² | Trockenbauarbeiten | Wand | Installationswand | Installationsraum |  |  | 0 | 1113HWa0813946794 |  |  |  | 0 |  |  | 0 | AllplanAttributes - Sicherheitsklasse: -
 | H2 Ebene 0 | WI-IW | 1113Wa 0813946797 | yes |  | m² | Trockenbauarbeiten | Wand | Installationswand | WI-IW |  |  | 0 | 1113HWa0813946794 |  |  |  | 0 |  |  | 0 | AllplanAttributes - W_Deckenanschluss: Gleitender Deckenanschluss Fall 01; ash_W_Trockenbau_Qualitäten: 11; Sicherheitsklasse: -
 | H2 Ebene 0 | Installationsraum | 1113Wa 0812443680 |  |  | m² | Trockenbauarbeiten | Wand |  |  |  |  | 0 | 1113HWa0812425745 |  |  |  | 0 |  |  | 0 | AllplanAttributes - Ortscode_Geschoßbezeichnung: E00; Sicherheitsklasse: -
 | H2 Ebene 0 | WI-VS | 1113Wa 0812443682 |  |  | m² | Trockenbauarbeiten | Wand |  |  |  |  | 0 | 1113HWa0812425745 |  |  |  | 0 |  |  | 0 | AllplanAttributes - Ortscode_Geschoßbezeichnung: E00; W_Deckenanschluss: Gleitender Deckenanschluss Fall 01; ash_W_Trockenbau_Qualitäten: 2; Sicherheitsklasse: -
 | H2 Ebene 0 | WI-LB | 1113Wa 0812439854 | yes |  | m² | Trockenbauarbeiten | Wand | Innenwand 1-Schalig | WI-LB |  |  | 0 | 1113HWa0812438661 |  |  |  | 0 |  |  | 47 | AllplanAttributes - ash_W_Trockenbau_Qualitäten: 8; Sicherheitsklasse: -
 | H2 Ebene 0 | Installationsraum | 1113Wa 0813143569 | yes |  | m² | Trockenbauarbeiten | Wand | Innenwand 1-Schalig | Installationsraum |  |  | 0 | 1113HWa0812438661 |  |  |  | 0 |  |  | 47 | AllplanAttributes - Sicherheitsklasse: -
 | H2 Ebene 0 | WI-HW 60 | 1113Wa 0813419265 | yes |  | m² | Zimmer- und Holzbauarbeiten | Wand | Innenwand 1-Schalig | WI-HW 60 |  |  | 0 | 1113HWa0812438661 |  |  |  | 0 |  |  | 47 | AllplanAttributes - Sicherheitsklasse: -
 | H2 Ebene 0 | WI-HW 60 | 1113Wa 0812488027 | yes |  | m² | Zimmer- und Holzbauarbeiten | Wand | Innenwand 1-Schalig | WI-HW 60 |  |  | 0 | 1113HWa0812488025 |  |  |  | 0 |  |  | 47 | AllplanAttributes - Sicherheitsklasse: -
 | H2 Ebene 0 | Installationsraum | 1113Wa 0813143258 | yes |  | m² | Trockenbauarbeiten | Wand | Innenwand 1-Schalig | Installationsraum |  |  | 0 | 1113HWa0812488025 |  |  |  | 0 |  |  | 47 | AllplanAttributes - Sicherheitsklasse: -
 | H2 Ebene 0 | WI-LB | 1113Wa 0813419439 | yes |  | m² | Trockenbauarbeiten | Wand | Innenwand 1-Schalig | WI-LB |  |  | 0 | 1113HWa0812488025 |  |  |  | 0 |  |  | 47 | AllplanAttributes - ash_W_Trockenbau_Qualitäten: 8; Sicherheitsklasse: -
 | H2 Ebene 0 | WI-LB | 1113Wa 0814113196 | yes |  | m² | Trockenbauarbeiten | Wand | Innenwand 1-Schalig | WI-LB |  |  | 0 | 1113HWa0814113195 | NEW |  |  |  |  |  | 0 | AllplanAttributes - W_Deckenanschluss: Gleitender Deckenanschluss Fall 01; ash_W_Trockenbau_Qualitäten: 18
 | H2 Ebene 0 | WI-LB | 1113Wa 0814113186 | yes |  | m² | Trockenbauarbeiten | Wand | Innenwand 1-Schalig | WI-LB |  |  | 0 | 1113HWa0814113185 | NEW |  |  |  |  |  | 0 | AllplanAttributes - W_Deckenanschluss: Gleitender Deckenanschluss Fall 01; ash_W_Trockenbau_Qualitäten: 18
 | H2 Ebene 0 | WI-LB | 1113Wa 0814113279 | yes |  | m² | Trockenbauarbeiten | Wand | Innenwand 1-Schalig | WI-LB |  |  | 0 | 1113HWa0814113278 | NEW |  |  |  |  |  | 0 | AllplanAttributes - W_Deckenanschluss: Gleitender Deckenanschluss Fall 01; ash_W_Trockenbau_Qualitäten: 18
 | H2 Ebene 0 | WI-LB | 1113Wa 0814113269 | yes |  | m² | Trockenbauarbeiten | Wand | Innenwand 1-Schalig | WI-LB |  |  | 0 | 1113HWa0814113268 | NEW |  |  |  |  |  | 0 | AllplanAttributes - W_Deckenanschluss: Gleitender Deckenanschluss Fall 01; ash_W_Trockenbau_Qualitäten: 18
 | H2 Ebene 0 | WI-LB | 1113Wa 0814108677 | yes |  | m² | Trockenbauarbeiten | Wand | Innenwand 1-Schalig | WI-LB |  |  | 0 | 1113HWa0814108676 | NEW |  |  |  |  |  | 0 | AllplanAttributes - W_Deckenanschluss: Gleitender Deckenanschluss Fall 01; ash_W_Trockenbau_Qualitäten: 18
 | H2 Ebene 0 | WI-LB | 1113Wa 0814108694 | yes |  | m² | Trockenbauarbeiten | Wand | Innenwand 1-Schalig | WI-LB |  |  | 0 | 1113HWa0814108693 | NEW |  |  |  |  |  | 0 | AllplanAttributes - W_Deckenanschluss: Gleitender Deckenanschluss Fall 01; ash_W_Trockenbau_Qualitäten: 18
 | H2 Ebene 0 | WI-LB | 1113Wa 0814108713 | yes |  | m² | Trockenbauarbeiten | Wand | Innenwand 1-Schalig | WI-LB |  |  | 0 | 1113HWa0814108712 | NEW |  |  |  |  |  | 0 | AllplanAttributes - W_Deckenanschluss: Gleitender Deckenanschluss Fall 01; ash_W_Trockenbau_Qualitäten: 18
 | H2 Ebene 0 | WI-LB | 1113Wa 0814108723 | yes |  | m² | Trockenbauarbeiten | Wand | Innenwand 1-Schalig | WI-LB |  |  | 0 | 1113HWa0814108722 | NEW |  |  |  |  |  | 0 | AllplanAttributes - W_Deckenanschluss: Gleitender Deckenanschluss Fall 01; ash_W_Trockenbau_Qualitäten: 18
 | H2 Ebene 0 | WI-LB | 1113Wa 0813264974 | yes |  | m² | Trockenbauarbeiten | Wand | Innenwand 1-Schalig | WI-LB |  |  | 0 | 1113HWa0813264829 | NEW |  |  | 0 |  |  | 0 | AllplanAttributes - W_Deckenanschluss: Gleitender Deckenanschluss Fall 01; ash_W_Trockenbau_Qualitäten: 12b; Sicherheitsklasse: -
 | H2 Ebene 0 | WI-HW 60 | 1113Wa 0814214024 | yes |  | m² | Zimmer- und Holzbauarbeiten | Wand | Innenwand 1-Schalig | WI-HW 60 |  |  | 0 | 1113HWa0814214021 | NEW |  |  | 0 |  |  | 47 | AllplanAttributes - Sicherheitsklasse: -
 | H2 Ebene 0 | WI-HW 60 | 1113Wa 0814130111 |  |  | m² | Zimmer- und Holzbauarbeiten | Wand | Innenwand 1-Schalig | WI-HW 60 |  |  | 0 | 1113HWa0814129935 |  |  |  | 0 |  |  | 47 | AllplanAttributes - Sicherheitsklasse: -
 | H2 Ebene 0 | WI-LB | 1113Wa 0814130109 |  |  | m² | Trockenbauarbeiten | Wand | Innenwand 1-Schalig | WI-LB |  |  | 0 | 1113HWa0814129935 |  |  |  | 0 |  |  | 47 | AllplanAttributes - ash_W_Trockenbau_Qualitäten: 6; Sicherheitsklasse: -
 | H2 Ebene 0 | BS Beplankung | 1113Wa 0812812388 |  |  | m² | Trockenbauarbeiten | Wand | """""""""""""""BS-Beplankung; 2-fach Gipsfaserplatten""""""""""""""" | BS Beplankung |  |  | 0 | 1113HWa0812812387 |  |  |  |  |  |  | 0 | AllplanAttributes - Sicherheitsklasse: -
 | H2 Ebene 0 | BS Beplankung | 1113Wa 0812812293 |  |  | m² | Trockenbauarbeiten | Wand | """""""""""""""BS-Beplankung; 2-fach Gipsfaserplatten""""""""""""""" | BS Beplankung |  |  | 0 | 1113HWa0812812292 |  |  |  |  |  |  | 0 | AllplanAttributes - Sicherheitsklasse: -
 | H2 Ebene 0 | BS Beplankung | 1113Wa 0812812440 |  |  | m² | Trockenbauarbeiten | Wand | """""""""""""""BS-Beplankung; 2-fach Gipsfaserplatten""""""""""""""" | BS Beplankung |  |  | 0 | 1113HWa0812812439 |  |  |  |  |  |  | 0 | AllplanAttributes - Sicherheitsklasse: -
 | H2 Ebene 0 | BS Beplankung | 1113Wa 0812834501 |  |  | m² | Trockenbauarbeiten | Wand | """""""""""""""BS-Beplankung; 2-fach Gipsfaserplatten""""""""""""""" | BS Beplankung |  |  | 0 | 1113HWa0812834484 |  |  |  |  |  |  | 0 | AllplanAttributes - Sicherheitsklasse: -
 | H2 Ebene 0 | BS Beplankung | 1113Wa 0812834482 |  |  | m² | Trockenbauarbeiten | Wand | """""""""""""""BS-Beplankung; 2-fach Gipsfaserplatten""""""""""""""" | BS Beplankung |  |  | 0 | 1113HWa0812834478 |  |  |  |  |  |  | 0 | AllplanAttributes - Sicherheitsklasse: -
 | H2 Ebene 0 | BS Beplankung | 1113Wa 0812834458 |  |  | m² | Trockenbauarbeiten | Wand | """""""""""""""BS-Beplankung; 2-fach Gipsfaserplatten""""""""""""""" | BS Beplankung |  |  | 0 | 1113HWa0812834457 |  |  |  |  |  |  | 0 | AllplanAttributes - Sicherheitsklasse: -
 | H2 Ebene 0 | BS Beplankung | 1113Wa 0812812402 |  |  | m² | Trockenbauarbeiten | Wand | """""""""""""""BS-Beplankung; 2-fach Gipsfaserplatten""""""""""""""" | BS Beplankung |  |  | 0 | 1113HWa0812812401 |  |  |  |  |  |  | 0 | AllplanAttributes - Sicherheitsklasse: -
 | H2 Ebene 0 | BS Beplankung | 1113Wa 0812812307 |  |  | m² | Trockenbauarbeiten | Wand | """""""""""""""BS-Beplankung; 2-fach Gipsfaserplatten""""""""""""""" | BS Beplankung |  |  | 0 | 1113HWa0812812306 |  |  |  |  |  |  | 0 | AllplanAttributes - Sicherheitsklasse: -
 | H2 Ebene 0 | BS Beplankung | 1113Wa 0812812369 |  |  | m² | Trockenbauarbeiten | Wand | """""""""""""""BS-Beplankung; 2-fach Gipsfaserplatten""""""""""""""" | BS Beplankung |  |  | 0 | 1113HWa0812812368 |  |  |  |  |  |  | 0 | AllplanAttributes - Sicherheitsklasse: -
 | H2 Ebene 0 | BS Beplankung | 1113Wa 0812811194 |  |  | m² | Trockenbauarbeiten | Wand | """""""""""""""BS-Beplankung; 2-fach Gipsfaserplatten""""""""""""""" | BS Beplankung |  |  | 0 | 1113HWa0812811193 |  |  |  |  |  |  | 0 | AllplanAttributes - Sicherheitsklasse: -
 | H2 Ebene 0 | BS Beplankung | 1113Wa 0812834495 |  |  | m² | Trockenbauarbeiten | Wand | """""""""""""""BS-Beplankung; 2-fach Gipsfaserplatten""""""""""""""" | BS Beplankung |  |  | 0 | 1113HWa0812834487 |  |  |  |  |  |  | 0 | AllplanAttributes - Sicherheitsklasse: -
 | H2 Ebene 0 | BS Beplankung | 1113Wa 0812812281 |  |  | m² | Trockenbauarbeiten | Wand | """""""""""""""BS-Beplankung; 2-fach Gipsfaserplatten""""""""""""""" | BS Beplankung |  |  | 0 | 1113HWa0812812280 |  |  |  |  |  |  | 0 | AllplanAttributes - Sicherheitsklasse: -
 | H2 Ebene 0 | BS Beplankung | 1113Wa 0812834474 |  |  | m² | Trockenbauarbeiten | Wand | """""""""""""""BS-Beplankung; 2-fach Gipsfaserplatten""""""""""""""" | BS Beplankung |  |  | 0 | 1113HWa0812834468 |  |  |  |  |  |  | 0 | AllplanAttributes - Sicherheitsklasse: -
 | H2 Ebene 0 | BS Beplankung | 1113Wa 0812812472 |  |  | m² | Trockenbauarbeiten | Wand | """""""""""""""BS-Beplankung; 2-fach Gipsfaserplatten""""""""""""""" | BS Beplankung |  |  | 0 | 1113HWa0812812471 |  |  |  |  |  |  | 0 | AllplanAttributes - Sicherheitsklasse: -
 | H2 Ebene 0 | BS Beplankung | 1113Wa 0812834493 |  |  | m² | Trockenbauarbeiten | Wand | """""""""""""""BS-Beplankung; 2-fach Gipsfaserplatten""""""""""""""" | BS Beplankung |  |  | 0 | 1113HWa0812834488 |  |  |  |  |  |  | 0 | AllplanAttributes - Sicherheitsklasse: -
 | H2 Ebene 0 | BS Beplankung | 1113Wa 0812834492 |  |  | m² | Trockenbauarbeiten | Wand | """""""""""""""BS-Beplankung; 2-fach Gipsfaserplatten""""""""""""""" | BS Beplankung |  |  | 0 | 1113HWa0812834486 |  |  |  |  |  |  | 0 | AllplanAttributes - Sicherheitsklasse: -
 | H2 Ebene 0 | BS Beplankung | 1113Wa 0812812484 |  |  | m² | Trockenbauarbeiten | Wand | """""""""""""""BS-Beplankung; 2-fach Gipsfaserplatten""""""""""""""" | BS Beplankung |  |  | 0 | 1113HWa0812812483 |  |  |  |  |  |  | 0 | AllplanAttributes - Sicherheitsklasse: -
 | H2 Ebene 0 | BS Beplankung | 1113Wa 0812834463 |  |  | m² | Trockenbauarbeiten | Wand | """""""""""""""BS-Beplankung; 2-fach Gipsfaserplatten""""""""""""""" | BS Beplankung |  |  | 0 | 1113HWa0812834454 |  |  |  |  |  |  | 0 | AllplanAttributes - Sicherheitsklasse: -
 | H2 Ebene 0 | BS Beplankung | 1113Wa 0812834460 |  |  | m² | Trockenbauarbeiten | Wand | """""""""""""""BS-Beplankung; 2-fach Gipsfaserplatten""""""""""""""" | BS Beplankung |  |  | 0 | 1113HWa0812834455 |  |  |  |  |  |  | 0 | AllplanAttributes - Sicherheitsklasse: -
 | H2 Ebene 0 | BS Beplankung | 1113Wa 0812812428 |  |  | m² | Trockenbauarbeiten | Wand | """""""""""""""BS-Beplankung; 2-fach Gipsfaserplatten""""""""""""""" | BS Beplankung |  |  | 0 | 1113HWa0812812427 |  |  |  |  |  |  | 0 | AllplanAttributes - Sicherheitsklasse: -
 | H2 Ebene 0 | BS Beplankung | 1113Wa 0812834505 |  |  | m² | Trockenbauarbeiten | Wand | """""""""""""""BS-Beplankung; 2-fach Gipsfaserplatten""""""""""""""" | BS Beplankung |  |  | 0 | 1113HWa0812834479 |  |  |  |  |  |  | 0 | AllplanAttributes - Sicherheitsklasse: -
 | H2 Ebene 0 | BS Beplankung | 1113Wa 0812812465 |  |  | m² | Trockenbauarbeiten | Wand | """""""""""""""BS-Beplankung; 2-fach Gipsfaserplatten""""""""""""""" | BS Beplankung |  |  | 0 | 1113HWa0812812464 |  |  |  |  |  |  | 0 | AllplanAttributes - Sicherheitsklasse: -
 | H2 Ebene 0 | BS Beplankung | 1113Wa 0812834472 |  |  | m² | Trockenbauarbeiten | Wand | """""""""""""""BS-Beplankung; 2-fach Gipsfaserplatten""""""""""""""" | BS Beplankung |  |  | 0 | 1113HWa0812834469 |  |  |  |  |  |  | 0 | AllplanAttributes - Sicherheitsklasse: -
 | H2 Ebene 0 | BS Beplankung | 1113Wa 0812834503 |  |  | m² | Trockenbauarbeiten | Wand | """""""""""""""BS-Beplankung; 2-fach Gipsfaserplatten""""""""""""""" | BS Beplankung |  |  | 0 | 1113HWa0812834480 |  |  |  |  |  |  | 0 | AllplanAttributes - Sicherheitsklasse: -
 | H2 Ebene 0 | BS Beplankung | 1113Wa 0812834471 |  |  | m² | Trockenbauarbeiten | Wand | """""""""""""""BS-Beplankung; 2-fach Gipsfaserplatten""""""""""""""" | BS Beplankung |  |  | 0 | 1113HWa0812834466 |  |  |  |  |  |  | 0 | AllplanAttributes - Sicherheitsklasse: -
 | H2 Ebene 0 | BS Beplankung | 1113Wa 0812834465 |  |  | m² | Trockenbauarbeiten | Wand | """""""""""""""BS-Beplankung; 2-fach Gipsfaserplatten""""""""""""""" | BS Beplankung |  |  | 0 | 1113HWa0812834456 |  |  |  |  |  |  | 0 | AllplanAttributes - Sicherheitsklasse: -
 | H2 Ebene 0 | BS Beplankung | 1113Wa 0812834499 |  |  | m² | Trockenbauarbeiten | Wand | """""""""""""""BS-Beplankung; 2-fach Gipsfaserplatten""""""""""""""" | BS Beplankung |  |  | 0 | 1113HWa0812834485 |  |  |  |  |  |  | 0 | AllplanAttributes - Sicherheitsklasse: -
 | H2 Ebene 0 | BS Beplankung | 1113Wa 0812834497 |  |  | m² | Trockenbauarbeiten | Wand | """""""""""""""BS-Beplankung; 2-fach Gipsfaserplatten""""""""""""""" | BS Beplankung |  |  | 0 | 1113HWa0812834483 |  |  |  |  |  |  | 0 | AllplanAttributes - Sicherheitsklasse: -
 | H2 Ebene 0 | BS Beplankung | 1113Wa 0812812421 |  |  | m² | Trockenbauarbeiten | Wand | """""""""""""""BS-Beplankung; 2-fach Gipsfaserplatten""""""""""""""" | BS Beplankung |  |  | 0 | 1113HWa0812812420 |  |  |  |  |  |  | 0 | AllplanAttributes - Sicherheitsklasse: -
 | H2 Ebene 0 | WI-STB | 1113Wa 0812447396 | yes |  | m² | Zimmer- und Holzbauarbeiten | Wand | Innenwand 1-Schalig | WI-STB |  |  | 0 | 1113HWa0812430804 | NEW |  |  | 0 |  |  | 42 | AllplanAttributes - Sicherheitsklasse: -
 | H2 Ebene 0 | WI-LB | 1113Wa 0814156609 |  |  | m² | Trockenbauarbeiten | Wand | Innenwand 1-Schalig | WI-LB |  |  | 0 | 1113HWa0812430804 | OTHER |  |  | 0 | AllplanAttributes - ash_W_Trockenbau_Qualitäten: 9; Sicherheitsklasse: -
 | H2 Ebene 0 | BS Beplankung | 1113Wa 0814206304 | yes |  | m² | Tischlerarbeiten | Wand | Innenwand 1-Schalig | BS Beplankung |  |  | 0 | 1113HWa0814206303 | NEW | no |  | 0 |  |  | 0 | AllplanAttributes - W_Deckenanschluss: Gleitender Deckenanschluss Fall 01; ash_W_Trockenbau_Qualitäten: 1
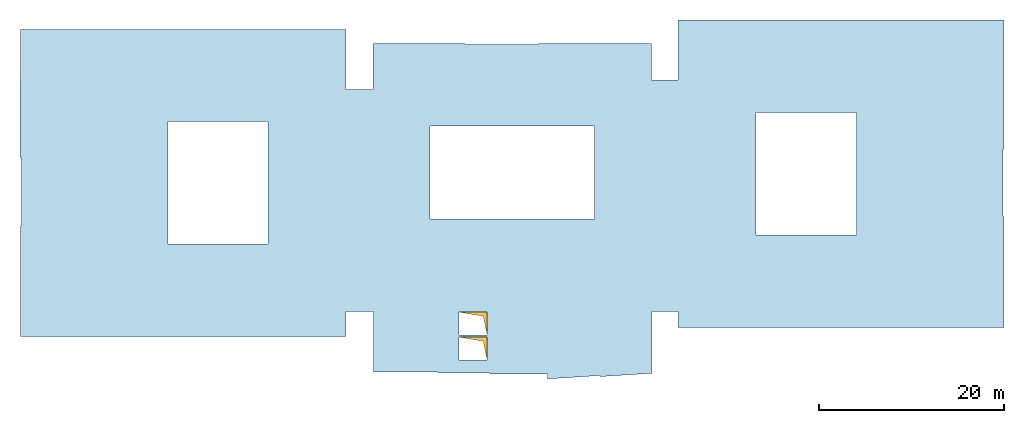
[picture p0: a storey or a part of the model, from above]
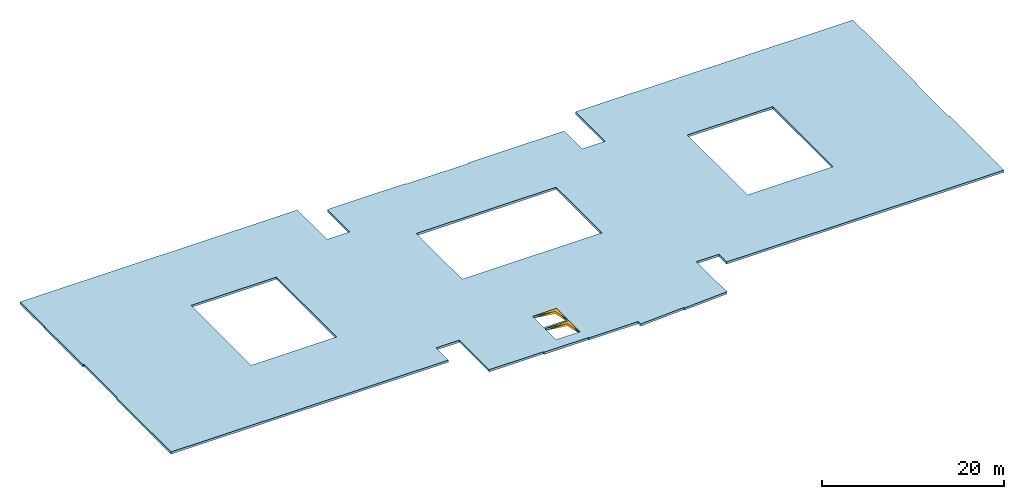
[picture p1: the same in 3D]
Properties of the parts of a building model (IFC4), part 76 of 80

# IfcWall (6826)
Name | In | Material | Allright_Bauteil_ID | 2D Interaktion | Codetext | Abrechnungsart | Gewerk | Objektname | Bezeichnung | AllplanAttributes, Material | Typ = SurfaceSpreadOfFlame | Brandschutzklasse | OKFF | P_ID | Status | LoadBearing | IsExternal | FireRating | ThermalTransmittance (W/K/m2) | Combustible | AcousticRating | Compartmentation | Reference
 | H2 Ebene 0 | WI-RIR | 1113Wa 0814182818 | yes |  | m² | Tischlerarbeiten | Wand | Innenwand 1-Schalig | WI-RIR |  |  | 0 | 1113HWa0814206303 | NEW | no |  | 0 |  |  | 0 | AllplanAttributes - W_Deckenanschluss: Gleitender Deckenanschluss Fall 01; ash_W_Trockenbau_Qualitäten: 1
 | H2 Ebene 0 | WI-RIR | 1113Wa 0814205664 | yes |  | m² | Tischlerarbeiten | Wand | Innenwand 1-Schalig | WI-RIR |  |  | 0 | 1113HWa0814206303 | NEW | no |  | 0 |  |  | 0 | AllplanAttributes - W_Deckenanschluss: Gleitender Deckenanschluss Fall 01; ash_W_Trockenbau_Qualitäten: 1
 | H2 Ebene 0 | WI-RIR | 1113Wa 0814205687 | yes |  | m² | Tischlerarbeiten | Wand | Innenwand 1-Schalig | WI-RIR |  |  | 0 | 1113HWa0814206303 | NEW | no |  | 0 |  |  | 0 | AllplanAttributes - W_Deckenanschluss: Gleitender Deckenanschluss Fall 01; ash_W_Trockenbau_Qualitäten: 1
 | H2 Ebene 0 | WI-RIR | 1113Wa 0814205673 | yes |  | m² | Tischlerarbeiten | Wand | Innenwand 1-Schalig | WI-RIR |  |  | 0 | 1113HWa0814206303 | NEW | no |  | 0 |  |  | 0 | AllplanAttributes - W_Deckenanschluss: Gleitender Deckenanschluss Fall 01; ash_W_Trockenbau_Qualitäten: 1
 | H2 Ebene 0 | BS Beplankung | 1113Wa 0814205740 | yes |  | m² | Tischlerarbeiten | Wand | Innenwand 1-Schalig | BS Beplankung |  |  | 0 | 1113HWa0814206303 | NEW | no |  | 0 |  |  | 0 | AllplanAttributes - W_Deckenanschluss: Gleitender Deckenanschluss Fall 01; ash_W_Trockenbau_Qualitäten: 1
 | H2 Ebene 0 | BS Beplankung | 1113Wa 0814205766 | yes |  | m² | Tischlerarbeiten | Wand | Innenwand 1-Schalig | BS Beplankung |  |  | 0 | 1113HWa0814206303 | NEW | no |  | 0 |  |  | 0 | AllplanAttributes - W_Deckenanschluss: Gleitender Deckenanschluss Fall 01; ash_W_Trockenbau_Qualitäten: 1
 | H2 Ebene 0 | BS Beplankung | 1113Wa 0814205733 | yes |  | m² | Tischlerarbeiten | Wand | Innenwand 1-Schalig | BS Beplankung |  |  | 0 | 1113HWa0814206303 | NEW | no |  | 0 |  |  | 0 | AllplanAttributes - W_Deckenanschluss: Gleitender Deckenanschluss Fall 01; ash_W_Trockenbau_Qualitäten: 1
 | H2 Ebene 0 | BS Beplankung | 1113Wa 0814205752 | yes |  | m² | Tischlerarbeiten | Wand | Innenwand 1-Schalig | BS Beplankung |  |  | 0 | 1113HWa0814206303 | NEW | no |  | 0 |  |  | 0 | AllplanAttributes - W_Deckenanschluss: Gleitender Deckenanschluss Fall 01; ash_W_Trockenbau_Qualitäten: 1
 | H2 Ebene 0 | WI-RIR | 1113Wa 0814206084 | yes |  | m² | Tischlerarbeiten | Wand | Innenwand 1-Schalig | WI-RIR |  |  | 0 | 1113HWa0814206303 | NEW | no |  | 0 |  |  | 0 | AllplanAttributes - W_Deckenanschluss: Gleitender Deckenanschluss Fall 01; ash_W_Trockenbau_Qualitäten: 1
 | H2 Ebene 0 | WI-RIR | 1113Wa 0814206116 | yes |  | m² | Tischlerarbeiten | Wand | Innenwand 1-Schalig | WI-RIR |  |  | 0 | 1113HWa0814206303 | NEW | no |  | 0 |  |  | 0 | AllplanAttributes - W_Deckenanschluss: Gleitender Deckenanschluss Fall 01; ash_W_Trockenbau_Qualitäten: 1
 | H2 Ebene 0 | WI-RIR | 1113Wa 0814206079 | yes |  | m² | Tischlerarbeiten | Wand | Innenwand 1-Schalig | WI-RIR |  |  | 0 | 1113HWa0814206303 | NEW | no |  | 0 |  |  | 0 | AllplanAttributes - W_Deckenanschluss: Gleitender Deckenanschluss Fall 01; ash_W_Trockenbau_Qualitäten: 1
 | H2 Ebene 0 | WI-RIR | 1113Wa 0814206098 | yes |  | m² | Tischlerarbeiten | Wand | Innenwand 1-Schalig | WI-RIR |  |  | 0 | 1113HWa0814206303 | NEW | no |  | 0 |  |  | 0 | AllplanAttributes - W_Deckenanschluss: Gleitender Deckenanschluss Fall 01; ash_W_Trockenbau_Qualitäten: 1
 | H2 Ebene 0 | BS Beplankung | 1113Wa 0814206151 | yes |  | m² | Tischlerarbeiten | Wand | Innenwand 1-Schalig | BS Beplankung |  |  | 0 | 1113HWa0814206303 | NEW | no |  | 0 |  |  | 0 | AllplanAttributes - W_Deckenanschluss: Gleitender Deckenanschluss Fall 01; ash_W_Trockenbau_Qualitäten: 1
 | H2 Ebene 0 | BS Beplankung | 1113Wa 0814206181 | yes |  | m² | Tischlerarbeiten | Wand | Innenwand 1-Schalig | BS Beplankung |  |  | 0 | 1113HWa0814206303 | NEW | no |  | 0 |  |  | 0 | AllplanAttributes - W_Deckenanschluss: Gleitender Deckenanschluss Fall 01; ash_W_Trockenbau_Qualitäten: 1
 | H2 Ebene 0 | BS Beplankung | 1113Wa 0814206144 | yes |  | m² | Tischlerarbeiten | Wand | Innenwand 1-Schalig | BS Beplankung |  |  | 0 | 1113HWa0814206303 | NEW | no |  | 0 |  |  | 0 | AllplanAttributes - W_Deckenanschluss: Gleitender Deckenanschluss Fall 01; ash_W_Trockenbau_Qualitäten: 1
 | H2 Ebene 0 | BS Beplankung | 1113Wa 0814206165 | yes |  | m² | Tischlerarbeiten | Wand | Innenwand 1-Schalig | BS Beplankung |  |  | 0 | 1113HWa0814206303 | NEW | no |  | 0 |  |  | 0 | AllplanAttributes - W_Deckenanschluss: Gleitender Deckenanschluss Fall 01; ash_W_Trockenbau_Qualitäten: 1
 | H2 Ebene 0 | BS Beplankung | 1113Wa 0814206234 | yes |  | m² | Tischlerarbeiten | Wand | Innenwand 1-Schalig | BS Beplankung |  |  | 0 | 1113HWa0814206303 | NEW | no |  | 0 |  |  | 0 | AllplanAttributes - W_Deckenanschluss: Gleitender Deckenanschluss Fall 01; ash_W_Trockenbau_Qualitäten: 1
 | H2 Ebene 0 | BS Beplankung | 1113Wa 0814206309 | yes |  | m² | Tischlerarbeiten | Wand | Innenwand 1-Schalig | BS Beplankung |  |  | 0 | 1113HWa0814206303 | NEW | no |  | 0 |  |  | 0 | AllplanAttributes - W_Deckenanschluss: Gleitender Deckenanschluss Fall 01; ash_W_Trockenbau_Qualitäten: 1
 | H2 Ebene 0 | BS Beplankung | 1113Wa 0814206331 | yes |  | m² | Tischlerarbeiten | Wand | Innenwand 1-Schalig | BS Beplankung |  |  | 0 | 1113HWa0814206303 | NEW | no |  | 0 |  |  | 0 | AllplanAttributes - W_Deckenanschluss: Gleitender Deckenanschluss Fall 01; ash_W_Trockenbau_Qualitäten: 1
 | H2 Ebene 0 | BS Beplankung | 1113Wa 0814206319 | yes |  | m² | Tischlerarbeiten | Wand | Innenwand 1-Schalig | BS Beplankung |  |  | 0 | 1113HWa0814206303 | NEW | no |  | 0 |  |  | 0 | AllplanAttributes - W_Deckenanschluss: Gleitender Deckenanschluss Fall 01; ash_W_Trockenbau_Qualitäten: 1
 | H2 Ebene 0 | BS Beplankung | 1113Wa 0814206207 | yes |  | m² | Tischlerarbeiten | Wand | Innenwand 1-Schalig | BS Beplankung |  |  | 0 | 1113HWa0814206303 | NEW | no |  | 0 |  |  | 0 | AllplanAttributes - W_Deckenanschluss: Gleitender Deckenanschluss Fall 01; ash_W_Trockenbau_Qualitäten: 1
 | H2 Ebene 0 | BS Beplankung | 1113Wa 0814206212 | yes |  | m² | Tischlerarbeiten | Wand | Innenwand 1-Schalig | BS Beplankung |  |  | 0 | 1113HWa0814206303 | NEW | no |  | 0 |  |  | 0 | AllplanAttributes - W_Deckenanschluss: Gleitender Deckenanschluss Fall 01; ash_W_Trockenbau_Qualitäten: 1
 | H2 Ebene 0 | BS Beplankung | 1113Wa 0814206222 | yes |  | m² | Tischlerarbeiten | Wand | Innenwand 1-Schalig | BS Beplankung |  |  | 0 | 1113HWa0814206303 | NEW | no |  | 0 |  |  | 0 | AllplanAttributes - W_Deckenanschluss: Gleitender Deckenanschluss Fall 01; ash_W_Trockenbau_Qualitäten: 1
 | H2 Ebene 0 | BS Beplankung | 1113Wa 0814207064 | yes |  | m² | Tischlerarbeiten | Wand | Innenwand 1-Schalig | BS Beplankung |  |  | 0 | 1113HWa0814206303 | NEW | no |  | 0 |  |  | 0 | AllplanAttributes - W_Deckenanschluss: Gleitender Deckenanschluss Fall 01; ash_W_Trockenbau_Qualitäten: 1
 | H2 Ebene 0 | BS Beplankung | 1113Wa 0814207068 | yes |  | m² | Tischlerarbeiten | Wand | Innenwand 1-Schalig | BS Beplankung |  |  | 0 | 1113HWa0814206303 | NEW | no |  | 0 |  |  | 0 | AllplanAttributes - W_Deckenanschluss: Gleitender Deckenanschluss Fall 01; ash_W_Trockenbau_Qualitäten: 1
 | H2 Ebene 0 | BS Beplankung | 1113Wa 0814207086 | yes |  | m² | Tischlerarbeiten | Wand | Innenwand 1-Schalig | BS Beplankung |  |  | 0 | 1113HWa0814206303 | NEW | no |  | 0 |  |  | 0 | AllplanAttributes - W_Deckenanschluss: Gleitender Deckenanschluss Fall 01; ash_W_Trockenbau_Qualitäten: 1
 | H2 Ebene 0 | WI-HW 60 | 1113Wa 0812551342 |  |  | m² | Zimmer- und Holzbauarbeiten | Wand | Innenwand 1-Schalig | WI-HW 60 |  |  | 0 | 1113HWa0812551330 |  |  |  | 0 |  |  | 0 | AllplanAttributes - Sicherheitsklasse: -
 | H2 Ebene 0 | WI-LW 60 | 1113Wa 0813854360 | yes |  | m² | Trockenbauarbeiten | Wand | Innenwand 1-Schalig | WI-LW 60 |  |  | 0 | 1113HWa0813854291 |  |  |  | 0 | AllplanAttributes - W_Deckenanschluss: Gleitender Deckenanschluss Fall 01; ash_W_Trockenbau_Qualitäten: 12c; Sicherheitsklasse: -
 | H2 Ebene 0 | Installationsraum | 1113Wa 0812926873 | yes |  | m² | Trockenbauarbeiten | Wand | Installationswand | Installationsraum |  |  | 0 | 1113HWa0812926868 | NEW |  |  | 0 |  |  | 0 | AllplanAttributes - Sicherheitsklasse: -
 | H2 Ebene 0 | WI-VS | 1113Wa 0812926871 | yes |  | m² | Trockenbauarbeiten | Wand | Installationswand | WI-VS |  |  | 0 | 1113HWa0812926868 | NEW |  |  | 0 |  |  | 0 | AllplanAttributes - W_Deckenanschluss: Gleitender Deckenanschluss Fall 01; ash_W_Trockenbau_Qualitäten: 2; Sicherheitsklasse: -
 | H2 Ebene 0 | Installationsraum | 1113Wa 0812447419 | yes |  | m² | Trockenbauarbeiten | Wand | Installationswand | Installationsraum |  |  | 0 | 1113HWa0812435127 | NEW |  |  | 0 |  |  | 0 | AllplanAttributes - Sicherheitsklasse: -
 | H2 Ebene 0 | WI-VS | 1113Wa 0812447423 | yes |  | m² | Trockenbauarbeiten | Wand | Installationswand | WI-VS |  |  | 0 | 1113HWa0812435127 | NEW |  |  | 0 |  |  | 0 | AllplanAttributes - W_Deckenanschluss: Gleitender Deckenanschluss Fall 01; ash_W_Trockenbau_Qualitäten: 2; Sicherheitsklasse: -
 | H2 Ebene 0 | WI-LB | 1113Wa 0814218672 |  |  | m² | Trockenbauarbeiten | Wand | Innenwand 1-Schalig | WI-LB |  |  | 0 | 1113HWa0812754839 |  |  |  | 0 |  |  | 47 | AllplanAttributes - ash_W_Trockenbau_Qualitäten: 8; Sicherheitsklasse: -
 | H2 Ebene 0 | Installationsraum | 1113Wa 0814218674 |  |  | m² | Trockenbauarbeiten | Wand | Innenwand 1-Schalig | Installationsraum |  |  | 0 | 1113HWa0812754839 |  |  |  | 0 |  |  | 47 | AllplanAttributes - Sicherheitsklasse: -
 | H2 Ebene 0 | WI-HW 60 | 1113Wa 0814218677 |  |  | m² | Zimmer- und Holzbauarbeiten | Wand | Innenwand 1-Schalig | WI-HW 60 |  |  | 0 | 1113HWa0812754839 |  |  |  | 0 |  |  | 47 | AllplanAttributes - Sicherheitsklasse: -
 | H2 Ebene 0 | WI-LB | 1113Wa 0812444170 | yes |  | m² | Trockenbauarbeiten | Wand | Innenwand 1-Schalig | WI-LB |  |  | 0 | 1113HWa0812428824 | NEW |  |  | 0 |  |  | 47 | AllplanAttributes - W_Deckenanschluss: Gleitender Deckenanschluss Fall 01; ash_W_Trockenbau_Qualitäten: 1e; Sicherheitsklasse: -
 | H2 Ebene 0 | WI-LB | 1113Wa 0812516237 | yes |  | m² | Trockenbauarbeiten | Wand | Innenwand 1-Schalig | WI-LB |  |  | 0 | 1113HWa0812516229 | NEW |  |  | 0 |  |  | 47 | AllplanAttributes - W_Deckenanschluss: Gleitender Deckenanschluss Fall 01; ash_W_Trockenbau_Qualitäten: 1e; Sicherheitsklasse: -
 | H2 Ebene 0 | WI-LB | 1113Wa 0812439875 | yes |  | m² | Trockenbauarbeiten | Wand | Innenwand 1-Schalig | WI-LB |  |  | 0 | 1113HWa0812438517 | NEW |  |  | 0 |  |  | 47 | AllplanAttributes - W_Deckenanschluss: Gleitender Deckenanschluss Fall 01; ash_W_Trockenbau_Qualitäten: 1e; Sicherheitsklasse: -
 | H2 Ebene 0 | WI-LB | 1113Wa 0812524524 | yes |  | m² | Trockenbauarbeiten | Wand | Innenwand 1-Schalig | WI-LB |  |  | 0 | 1113HWa0812524516 | NEW |  |  | 0 |  |  | 47 | AllplanAttributes - W_Deckenanschluss: Gleitender Deckenanschluss Fall 01; ash_W_Trockenbau_Qualitäten: 1e; Sicherheitsklasse: -
WV 1.1 | H2 Ebene 0 |  | 1113Sma0814230769 |  | VUK1 - Gebäudefuge | St | Trockenbauarbeiten | SmartPart | WV 1.1 |  |  |  | 0.2 |  |  |  |  | - | AllplanAttributes - UK: 0 m; OK: 0 m; V6: 0 m; V7: 0 m; V8: 0 m; V9: 0; Länge: 1.24 m; Dicke: 0.025 m; Höhe: 0.25 m; Programmversion: 3.1; Text3: 0; Plugin_Bezeichnung: MainObject; Plugin_Objektname: SmartPartCompressed; Version: 1.1; Abstand_Öffn_Unten: 0 m; ash T_Feuchtebeständigkeit: nein; Feuerwiderstandsklasse~: nein
WV 1.1 | H2 Ebene 0 |  | 1113Sma0814230797 |  | VUK1 - Gebäudefuge | St | Trockenbauarbeiten | SmartPart | WV 1.1 |  |  |  | 0.2 |  |  |  |  | - | AllplanAttributes - UK: 0 m; OK: 0 m; V6: 0 m; V7: 0 m; V8: 0 m; V9: 0; Länge: 3.79 m; Dicke: 0.025 m; Höhe: 0.25 m; Programmversion: 3.1; Text3: 0; Plugin_Bezeichnung: MainObject; Plugin_Objektname: SmartPartCompressed; Version: 1.1; Abstand_Öffn_Unten: 0 m; ash T_Feuchtebeständigkeit: nein; Feuerwiderstandsklasse~: nein
WV 1.1 | H2 Ebene 0 |  | 1113Sma0814230820 |  | VUK1 - Gebäudefuge | St | Trockenbauarbeiten | SmartPart | WV 1.1 |  |  |  | 0.2 |  |  |  |  | - | AllplanAttributes - UK: 0 m; OK: 0 m; V6: 0 m; V7: 0 m; V8: 0 m; V9: 0; Länge: 1.21 m; Dicke: 0.025 m; Höhe: 0.25 m; Programmversion: 3.1; Text3: 0; Plugin_Bezeichnung: MainObject; Plugin_Objektname: SmartPartCompressed; Version: 1.1; Abstand_Öffn_Unten: 0 m; ash T_Feuchtebeständigkeit: nein; Feuerwiderstandsklasse~: nein
WV 1.1 | H2 Ebene 0 |  | 1113Sma0814230921 |  | VUK1 - Gebäudefuge | St | Trockenbauarbeiten | SmartPart | WV 1.1 |  |  |  | 0.2 |  |  |  |  | - | AllplanAttributes - UK: 0 m; OK: 0 m; V6: 0 m; V7: 0 m; V8: 0 m; V9: 0; Länge: 2.08 m; Dicke: 0.025 m; Höhe: 0.25 m; Programmversion: 3.1; Text3: 0; Plugin_Bezeichnung: MainObject; Plugin_Objektname: SmartPartCompressed; Version: 1.1; Abstand_Öffn_Unten: 0 m; ash T_Feuchtebeständigkeit: nein; Feuerwiderstandsklasse~: nein
WV 1.1 | H2 Ebene 0 |  | 1113Sma0814230934 |  | VUK1 - Gebäudefuge | St | Trockenbauarbeiten | SmartPart | WV 1.1 |  |  |  | 0.2 |  |  |  |  | - | AllplanAttributes - UK: 0 m; OK: 0 m; V6: 0 m; V7: 0 m; V8: 0 m; V9: 0; Länge: 0.64 m; Dicke: 0.025 m; Höhe: 0.25 m; Programmversion: 3.1; Text3: 0; Plugin_Bezeichnung: MainObject; Plugin_Objektname: SmartPartCompressed; Version: 1.1; Abstand_Öffn_Unten: 0 m; ash T_Feuchtebeständigkeit: nein; Feuerwiderstandsklasse~: nein
WV 1.1 | H2 Ebene 0 |  | 1113Sma0814230996 |  | VUK1 - Gebäudefuge | St | Trockenbauarbeiten | SmartPart | WV 1.1 |  |  |  | 0.2 |  |  |  |  | - | AllplanAttributes - UK: 0 m; OK: 0 m; V6: 0 m; V7: 0 m; V8: 0 m; V9: 0; Länge: 2.98 m; Dicke: 0.025 m; Höhe: 0.25 m; Programmversion: 3.1; Text3: 0; Plugin_Bezeichnung: MainObject; Plugin_Objektname: SmartPartCompressed; Version: 1.1; Abstand_Öffn_Unten: 0 m; ash T_Feuchtebeständigkeit: nein; Feuerwiderstandsklasse~: nein
WV 1.1 | H2 Ebene 0 |  | 1113Sma0814230947 |  | VUK1 - Gebäudefuge | St | Trockenbauarbeiten | SmartPart | WV 1.1 |  |  |  | 0.2 |  |  |  |  | - | AllplanAttributes - UK: 0 m; OK: 0 m; V6: 0 m; V7: 0 m; V8: 0 m; V9: 0; Länge: 0.27 m; Dicke: 0.025 m; Höhe: 0.25 m; Programmversion: 3.1; Text3: 0; Plugin_Bezeichnung: MainObject; Plugin_Objektname: SmartPartCompressed; Version: 1.1; Abstand_Öffn_Unten: 0 m; ash T_Feuchtebeständigkeit: nein; Feuerwiderstandsklasse~: nein
 | H2 Ebene 0 | WI-LW 60 | 1113Wa 0813393511 | yes |  | m² | Trockenbauarbeiten | Wand | Innenwand 1-Schalig | WI-LW 60 |  |  | 0 | 1113HWa0813393378 |  |  |  | 0 |  |  | 47 | AllplanAttributes - W_Deckenanschluss: Gleitender Deckenanschluss Fall 01; ash_W_Trockenbau_Qualitäten: 12b; Sicherheitsklasse: -
 | H2 Ebene 0 | WI-LB | 1113Wa 0814019676 | yes |  | m² | Trockenbauarbeiten | Wand | Innenwand 1-Schalig | WI-LB |  |  | 0 | 1113HWa0814019675 | NEW |  |  | 0 | AllplanAttributes - W_Deckenanschluss: Gleitender Deckenanschluss Fall 01; ash_W_Trockenbau_Qualitäten: 18; Sicherheitsklasse: -
 | H2 Ebene 0 | WI-LB | 1113Wa 0812980340 | yes |  | m² | Trockenbauarbeiten | Wand | Innenwand 1-Schalig | WI-LB |  |  | 0 | 1113HWa0812980338 |  |  |  |  |  |  | 0 | AllplanAttributes - ash_W_Trockenbau_Qualitäten: 8
 | H2 Ebene 0 | WI-LB | 1113Wa 0812980447 | yes |  | m² | Trockenbauarbeiten | Wand | Innenwand 1-Schalig | WI-LB |  |  | 0 | 1113HWa0812980445 |  |  |  |  |  |  | 0 | AllplanAttributes - ash_W_Trockenbau_Qualitäten: 8
 | H2 Ebene 0 | WI-LW 60 | 1113Wa 0813940656 | yes |  | m² | Trockenbauarbeiten | Wand | Innenwand 1-Schalig | WI-LW 60 |  |  | 0 | 1113HWa0813940655 | NEW | no |  | 0 | AllplanAttributes - Sicherheitsklasse: -
 | H2 Ebene 0 | BS Beplankung | 1113Wa 0814207244 | yes |  | m² | Tischlerarbeiten | Wand | Innenwand 1-Schalig | BS Beplankung |  |  | 0 | 1113HWa0814206303 | NEW | no |  | 0 |  |  | 0 | AllplanAttributes - ash_W_Trockenbau_Qualitäten: 1
 | H2 Ebene 0 | BS Beplankung | 1113Wa 0814207259 | yes |  | m² | Tischlerarbeiten | Wand | Innenwand 1-Schalig | BS Beplankung |  |  | 0 | 1113HWa0814206303 | NEW | no |  | 0 |  |  | 0 | AllplanAttributes - ash_W_Trockenbau_Qualitäten: 1
 | H2 Ebene 0 | BS Beplankung | 1113Wa 0814207249 | yes |  | m² | Tischlerarbeiten | Wand | Innenwand 1-Schalig | BS Beplankung |  |  | 0 | 1113HWa0814206303 | NEW | no |  | 0 |  |  | 0 | AllplanAttributes - ash_W_Trockenbau_Qualitäten: 1
 | H2 Ebene 0 | WI-LB | 1113Wa 0812542269 | yes |  | m² | Trockenbauarbeiten | Wand | Innenwand 1-Schalig | WI-LB |  |  | 0 | 1113HWa0812542251 |  |  |  | 0 |  |  | 0 | AllplanAttributes - Ortscode_Geschoßbezeichnung: E00; ash_W_Trockenbau_Qualitäten: 13; Sicherheitsklasse: -
 | H2 Ebene 0 | WI-LB | 1113Wa 0812439882 | yes |  | m² | Trockenbauarbeiten | Wand | Innenwand 1-Schalig | WI-LB |  |  | 0 | 1113HWa0812429054 |  |  |  | 0 |  |  | 47 | AllplanAttributes - ash_W_Trockenbau_Qualitäten: 17; Sicherheitsklasse: -
 | H2 Ebene 0 | Installationsraum | 1113Wa 0813144980 | yes |  | m² | Trockenbauarbeiten | Wand | Innenwand 1-Schalig | Installationsraum |  |  | 0 | 1113HWa0812429054 |  |  |  | 0 |  |  | 47 | AllplanAttributes - Sicherheitsklasse: -
 | H2 Ebene 0 | WI-HW 60 | 1113Wa 0813421301 | yes |  | m² | Zimmer- und Holzbauarbeiten | Wand | Innenwand 1-Schalig | WI-HW 60 |  |  | 0 | 1113HWa0812429054 |  |  |  | 0 |  |  | 47 | AllplanAttributes - Sicherheitsklasse: -
 | H2 Ebene 0 | WI-VS | 1113Wa 0813421302 | yes |  | m² | Trockenbauarbeiten | Wand | Innenwand 1-Schalig | WI-VS |  |  | 0 | 1113HWa0812429054 |  |  |  | 0 |  |  | 47 | AllplanAttributes - ash_W_Trockenbau_Qualitäten: 17; Sicherheitsklasse: -
 | H2 Ebene 0 | WI-LB | 1113Wa 0814166981 | yes |  | m² | Trockenbauarbeiten | Wand | Innenwand 1-Schalig | WI-LB |  |  | 0 | 1113HWa0814166980 | NEW |  |  | 0 |  |  | 0 | AllplanAttributes - ash_W_Trockenbau_Qualitäten: 13; Sicherheitsklasse: -
 | H2 Ebene 0 | WI-LB | 1113Wa 0813828263 | yes |  | m² | Trockenbauarbeiten | Wand | Innenwand 1-Schalig | WI-LB |  |  | 0 | 1113HWa0813828262 |  |  |  | 0 |  |  | 47 | AllplanAttributes - ash_W_Trockenbau_Qualitäten: 1b; Sicherheitsklasse: -
 | H2 Ebene 0 | WI-LB | 1113Wa 0812980261 | yes |  | m² | Trockenbauarbeiten | Wand | Innenwand 1-Schalig | WI-LB |  |  | 0 | 1113HWa0812980259 |  |  |  |  |  |  | 0 | AllplanAttributes - ash_W_Trockenbau_Qualitäten: 8
 | H2 Ebene 0 | WI-LW 60 | 1113Wa 0812440294 | yes |  | m² | Trockenbauarbeiten | Wand | Innenwand 1-Schalig | WI-LW 60 |  |  | 0 | 1113HWa0812428972 | NEW |  |  | 0 | AllplanAttributes - ash_W_Trockenbau_Qualitäten: 12a; Sicherheitsklasse: -
 | H2 Ebene 0 | WI-LB | 1113Wa 0812443166 | yes |  | m² | Trockenbauarbeiten | Wand | Innenwand 1-Schalig | WI-LB |  |  | 0 | 1113HWa0812425462 |  |  |  | 0 |  |  | 47 | AllplanAttributes - Ortscode_Geschoßbezeichnung: E00; ash_W_Trockenbau_Qualitäten: 1b; Sicherheitsklasse: -
 | H2 Ebene 0 | WI-LB | 1113Wa 0813046640 | yes |  | m² | Trockenbauarbeiten | Wand | Innenwand 1-Schalig | WI-LB |  |  | 0 | 1113HWa0813046639 |  |  |  |  |  |  | 0 | AllplanAttributes - ash_W_Trockenbau_Qualitäten: 16
 | H2 Ebene 0 | WI-LB | 1113Wa 0812980366 | yes |  | m² | Trockenbauarbeiten | Wand | Innenwand 1-Schalig | WI-LB |  |  | 0 | 1113HWa0812980364 |  |  |  |  |  |  | 0 | AllplanAttributes - ash_W_Trockenbau_Qualitäten: 8
 | H2 Ebene 0 | WI-LB | 1113Wa 0812542415 | yes |  | m² | Trockenbauarbeiten | Wand | Innenwand 1-Schalig | WI-LB |  |  | 0 | 1113HWa0812542405 |  |  |  | 0 |  |  | 0 | AllplanAttributes - Ortscode_Geschoßbezeichnung: E00; ash_W_Trockenbau_Qualitäten: 13; Sicherheitsklasse: -
 | H2 Ebene 0 | WI-LB | 1113Wa 0812980375 | yes |  | m² | Trockenbauarbeiten | Wand | Innenwand 1-Schalig | WI-LB |  |  | 0 | 1113HWa0812980373 |  |  |  |  |  |  | 0 | AllplanAttributes - ash_W_Trockenbau_Qualitäten: 8
 | H2 Ebene 0 | WI-LB | 1113Wa 0812543591 | yes |  | m² | Trockenbauarbeiten | Wand | Innenwand 1-Schalig | WI-LB |  |  | 0 | 1113HWa0812543589 |  |  |  | 0 |  |  | 0 | AllplanAttributes - Ortscode_Geschoßbezeichnung: E00; ash_W_Trockenbau_Qualitäten: 13; Sicherheitsklasse: -
 | H2 Ebene 0 | WI-LB | 1113Wa 0812447378 | yes |  | m² | Trockenbauarbeiten | Wand | Innenwand 1-Schalig | WI-LB |  |  | 0 | 1113HWa0812447232 | NEW |  |  | 0 | AllplanAttributes - ash_W_Trockenbau_Qualitäten: 9; Sicherheitsklasse: -
 | H2 Ebene 0 | WI-STB | 1113Wa 0812888839 | yes |  | m² | Betonarbeiten | Wand | Innenwand 1-Schalig | WI-STB |  |  | 0 | 1113HWa0812447232 | NEW |  |  | 0 |  |  | 42 | AllplanAttributes - Sicherheitsklasse: -
 | H2 Ebene 0 | WI-LB | 1113Wa 0814156308 | yes |  | m² | Trockenbauarbeiten | Wand | Innenwand 1-Schalig | WI-LB |  |  | 0 | 1113HWa0812447232 | NEW |  |  | 0 |  |  | 42 | AllplanAttributes - ash_W_Trockenbau_Qualitäten: 9; Sicherheitsklasse: -
 | H2 Ebene 0 | WI-IW | 1113Wa 0813046669 | yes |  | m² | Trockenbauarbeiten | Wand | Installationswand | WI-IW |  |  | 0 | 1113HWa0813046668 |  |  |  | 0 |  |  | 47 | AllplanAttributes - ash_W_Trockenbau_Qualitäten: 8; Sicherheitsklasse: -
 | H2 Ebene 0 | WI-LW 60 | 1113Wa 0812446937 | yes |  | m² | Trockenbauarbeiten | Wand | Innenwand 1-Schalig | WI-LW 60 |  |  | 0 | 1113HWa0812434291 | NEW |  |  | 0 | AllplanAttributes - ash_W_Trockenbau_Qualitäten: 12a; Sicherheitsklasse: -
 | H2 Ebene 0 | WI-LB | 1113Wa 0813046655 | yes |  | m² | Trockenbauarbeiten | Wand | Innenwand 1-Schalig | WI-LB |  |  | 0 | 1113HWa0813046654 |  |  |  |  |  |  | 0 | AllplanAttributes - ash_W_Trockenbau_Qualitäten: 16
 | H2 Ebene 0 | WI-LW 60 | 1113Wa 0813370687 | yes |  | m² | Trockenbauarbeiten | Wand | Innenwand 1-Schalig | WI-LW 60 |  |  | 0 | 1113HWa0813370551 |  |  |  | 0 |  |  | 47 | AllplanAttributes - ash_W_Trockenbau_Qualitäten: 12a; Sicherheitsklasse: -
 | H2 Ebene 0 | WI-LW 60 | 1113Wa 0812440009 | yes |  | m² | Trockenbauarbeiten | Wand | Innenwand 1-Schalig | WI-LW 60 |  |  | 0 | 1113HWa0812437927 | NEW |  |  | 0 | AllplanAttributes - ash_W_Trockenbau_Qualitäten: 12a; Sicherheitsklasse: -
 | H2 Ebene 0 | WI-LB | 1113Wa 0812934445 | yes |  | m² | Trockenbauarbeiten | Wand | Innenwand 1-Schalig | WI-LB |  |  | 0 | 1113HWa0812934444 |  |  |  | 0 |  |  | 0 | AllplanAttributes - Sicherheitsklasse: -
 | H2 Ebene 0 | WI-LB | 1113Wa 0812980292 | yes |  | m² | Trockenbauarbeiten | Wand | Innenwand 1-Schalig | WI-LB |  |  | 0 | 1113HWa0812980290 |  |  |  |  |  |  | 0 | AllplanAttributes - ash_W_Trockenbau_Qualitäten: 8
 | H2 Ebene 0 | WI-LB | 1113Wa 0812980227 | yes |  | m² | Trockenbauarbeiten | Wand | Innenwand 1-Schalig | WI-LB |  |  | 0 | 1113HWa0812980226 |  |  |  |  |  |  | 0 | AllplanAttributes - ash_W_Trockenbau_Qualitäten: 8
 | H2 Ebene 0 | WI-LB | 1113Wa 0812980301 | yes |  | m² | Trockenbauarbeiten | Wand | Innenwand 1-Schalig | WI-LB |  |  | 0 | 1113HWa0812980299 |  |  |  |  |  |  | 0 | AllplanAttributes - ash_W_Trockenbau_Qualitäten: 8
 | H2 Ebene 0 | WI-LB | 1113Wa 0812447387 | yes |  | m² | Trockenbauarbeiten | Wand | Innenwand 1-Schalig | WI-LB |  |  | 0 | 1113HWa0812437934 | OTHER |  |  | 0 | AllplanAttributes - ash_W_Trockenbau_Qualitäten: 6; Sicherheitsklasse: -
 | H2 Ebene 0 | WI-HW 60 | 1113Wa 0813450593 | yes |  | m² | Zimmer- und Holzbauarbeiten | Wand | Innenwand 1-Schalig | WI-HW 60 |  |  | 0 | 1113HWa0812437934 | NEW |  |  | 0 |  |  | 0 | AllplanAttributes - Sicherheitsklasse: -
 | H2 Ebene 0 | WI-LB | 1113Wa 0813936539 | yes |  | m² | Trockenbauarbeiten | Wand | Innenwand 1-Schalig | WI-LB |  |  | 0 | 1113HWa0812437934 | NEW |  |  | 0 |  |  | 0 | AllplanAttributes - ash_W_Trockenbau_Qualitäten: 16; Sicherheitsklasse: -
 | H2 Ebene 0 | WI-LB | 1113Wa 0813912996 | yes |  | m² | Trockenbauarbeiten | Wand | Innenwand 1-Schalig | WI-LB |  |  | 0 | 1113HWa0813912995 | NEW |  |  | 0 | AllplanAttributes - ash_W_Trockenbau_Qualitäten: 9; Sicherheitsklasse: -
 | H2 Ebene 0 | WI-IW | 1113Wa 0814234790 | yes |  | m² | Trockenbauarbeiten | Wand | Installationswand | WI-IW |  |  | 0 | 1113HWa0812464233 | NEW |  |  | 0 |  |  | 0 | AllplanAttributes - W_Deckenanschluss: Gleitender Deckenanschluss Fall 01; ash_W_Trockenbau_Qualitäten: 18; Sicherheitsklasse: -
 | H2 Ebene 0 | Installationsraum | 1113Wa 0814234791 | yes |  | m² | Trockenbauarbeiten | Wand | Installationswand | Installationsraum |  |  | 0 | 1113HWa0812464233 | NEW |  |  | 0 |  |  | 0 | AllplanAttributes - Sicherheitsklasse: -
WV 1.1 | H2 Ebene 0 |  | 1113Sma0814159378 |  | VUK1 - Hängeschrank | St | Trockenbauarbeiten | SmartPart | WV 1.1 |  |  |  | 0.2 |  |  |  |  | - | AllplanAttributes - Text1: WA2018; UK: 0 m; OK: 0 m; V6: 0 m; V7: 0 m; V8: 0 m; V9: 0; Länge: 1.5 m; Dicke: 0.025 m; Höhe: 0.2 m; Programmversion: 3.1; Text3: 0; Plugin_Bezeichnung: MainObject; Plugin_Objektname: SmartPartCompressed; Version: 1.1; Abstand_Öffn_Unten: 2.35 m; ash T_Feuchtebeständigkeit: nein; Feuerwiderstandsklasse~: nein
WV 1.1 | H2 Ebene 0 |  | 1113Sma0814159392 |  | VUK1 - Seifenspender | St | Trockenbauarbeiten | SmartPart | WV 1.1 |  |  |  | 0.2 |  |  |  |  | - | AllplanAttributes - Text1: WA2016; UK: 0 m; OK: 0 m; V6: 0 m; V7: 0 m; V8: 0 m; V9: 0; Länge: 0.2 m; Dicke: 0.025 m; Höhe: 0.3 m; Programmversion: 3.1; Text3: 0; Plugin_Bezeichnung: MainObject; Plugin_Objektname: SmartPartCompressed; Version: 1.1; Abstand_Öffn_Unten: 1.26 m; ash T_Feuchtebeständigkeit: nein; Feuerwiderstandsklasse~: nein
 | H2 Ebene 0 | WI-IW | 1113Wa 0814234746 | yes |  | m² | Trockenbauarbeiten | Wand | Installationswand | WI-IW |  |  | 0 | 1113HWa0812464233 | NEW |  |  | 0 |  |  | 0 | AllplanAttributes - W_Deckenanschluss: Gleitender Deckenanschluss Fall 01; ash_W_Trockenbau_Qualitäten: 18; Sicherheitsklasse: -
 | H2 Ebene 0 | Installationsraum | 1113Wa 0814234747 | yes |  | m² | Trockenbauarbeiten | Wand | Installationswand | Installationsraum |  |  | 0 | 1113HWa0812464233 | NEW |  |  | 0 |  |  | 0 | AllplanAttributes - Sicherheitsklasse: -
 | H2 Ebene 0 | WI-IW | 1113Wa 0814242589 | yes |  | m² | Trockenbauarbeiten | Wand | Installationswand | WI-IW |  |  | 0 | 1113HWa0812464233 | NEW |  |  | 0 |  |  | 0 | AllplanAttributes - W_Deckenanschluss: Gleitender Deckenanschluss Fall 01; ash_W_Trockenbau_Qualitäten: 18; Sicherheitsklasse: -
 | H2 Ebene 0 | Installationsraum | 1113Wa 0814242590 | yes |  | m² | Trockenbauarbeiten | Wand | Installationswand | Installationsraum |  |  | 0 | 1113HWa0812464233 | NEW |  |  | 0 |  |  | 0 | AllplanAttributes - Sicherheitsklasse: -
WV 1.1 | H2 Ebene 0 |  | 1113Sma0814159502 |  | VUK1 - Hängeschrank | St | Trockenbauarbeiten | SmartPart | WV 1.1 |  |  |  | 0.2 |  |  |  |  | - | AllplanAttributes - Text1: WA2009; UK: 0 m; OK: 0 m; V6: 0 m; V7: 0 m; V8: 0 m; V9: 0; Länge: 1.25 m; Dicke: 0.025 m; Höhe: 0.2 m; Programmversion: 3.1; Text3: 0; Plugin_Bezeichnung: MainObject; Plugin_Objektname: SmartPartCompressed; Version: 1.1; Abstand_Öffn_Unten: 2.35 m; ash T_Feuchtebeständigkeit: nein; Feuerwiderstandsklasse~: nein
WV 1.1 | H2 Ebene 0 |  | 1113Sma0814159488 |  | VUK1 - Wäschehalter | St | Trockenbauarbeiten | SmartPart | WV 1.1 |  |  |  | 0.2 |  |  |  |  | - | AllplanAttributes - Text1: WA2009; UK: 0 m; OK: 0 m; V6: 0 m; V7: 0 m; V8: 0 m; V9: 0; Länge: 1 m; Dicke: 0.025 m; Höhe: 0.2 m; Programmversion: 3.1; Text3: 0; Plugin_Bezeichnung: MainObject; Plugin_Objektname: SmartPartCompressed; Version: 1.1; Abstand_Öffn_Unten: 1.625 m; ash T_Feuchtebeständigkeit: nein; Feuerwiderstandsklasse~: nein
 | H2 Ebene 0 | WI-STB | 1113Wa 0812447095 | yes |  | m² | Zimmer- und Holzbauarbeiten | Wand | Außenwand 1-Schalig | WI-STB |  |  | 0 | 1113HWa0812430737 | NEW | no |  | 0 |  |  | 52 | AllplanAttributes - Sicherheitsklasse: -
 | H2 Ebene 0 | WI-IW | 1113Wa 0814242738 | yes |  | m² | Trockenbauarbeiten | Wand | Installationswand | WI-IW |  |  | 0 | 1113HWa0812464233 | NEW |  |  | 0 |  |  | 0 | AllplanAttributes - W_Deckenanschluss: Gleitender Deckenanschluss Fall 01; ash_W_Trockenbau_Qualitäten: 16; Sicherheitsklasse: -
 | H2 Ebene 0 | Installationsraum | 1113Wa 0814242739 | yes |  | m² | Trockenbauarbeiten | Wand | Installationswand | Installationsraum |  |  | 0 | 1113HWa0812464233 | NEW |  |  | 0 |  |  | 0 | AllplanAttributes - Sicherheitsklasse: -
 | H2 Ebene 0 | WI-STB | 1113Wa 0812544544 | yes |  | m² | Zimmer- und Holzbauarbeiten | Wand | Außenwand 1-Schalig | WI-STB |  |  | 0 | 1113HWa0812544535 | NEW | no |  | 0 |  |  | 52 | AllplanAttributes - Sicherheitsklasse: -
 | H2 Ebene 0 | WI-IW | 1113Wa 0814242849 | yes |  | m² | Trockenbauarbeiten | Wand | Installationswand | WI-IW |  |  | 0 | 1113HWa0812464233 | NEW |  |  | 0 |  |  | 0 | AllplanAttributes - W_Deckenanschluss: Gleitender Deckenanschluss Fall 01; ash_W_Trockenbau_Qualitäten: 16; Sicherheitsklasse: -
 | H2 Ebene 0 | Installationsraum | 1113Wa 0814242850 | yes |  | m² | Trockenbauarbeiten | Wand | Installationswand | Installationsraum |  |  | 0 | 1113HWa0812464233 | NEW |  |  | 0 |  |  | 0 | AllplanAttributes - Sicherheitsklasse: -
 | H2 Ebene 0 | WI-LB | 1113Wa 0812441654 | yes |  | m² | Trockenbauarbeiten | Wand | Innenwand 1-Schalig | WI-LB |  |  | 0 | 1113HWa0812440930 |  |  |  | 0 |  |  | 47 | AllplanAttributes - Ortscode_Geschoßbezeichnung: E00; W_Deckenanschluss: Gleitender Deckenanschluss Fall 03; ash_W_Trockenbau_Qualitäten: 1c; Sicherheitsklasse: -
 | H2 Ebene 0 | WI-LB | 1113Wa 0812441644 | yes |  | m² | Trockenbauarbeiten | Wand | Innenwand 1-Schalig | WI-LB |  |  | 0 | 1113HWa0812440932 |  |  |  | 0 |  |  | 47 | AllplanAttributes - Ortscode_Geschoßbezeichnung: E00; W_Deckenanschluss: Gleitender Deckenanschluss Fall 03; ash_W_Trockenbau_Qualitäten: 1c; Sicherheitsklasse: -
 | H2 Ebene 0 | WI-LB | 1113Wa 0812441664 | yes |  | m² | Trockenbauarbeiten | Wand | Innenwand 1-Schalig | WI-LB |  |  | 0 | 1113HWa0812440883 |  |  |  | 0 |  |  | 0 | AllplanAttributes - Ortscode_Geschoßbezeichnung: E00; W_Deckenanschluss: Gleitender Deckenanschluss Fall 03; ash_W_Trockenbau_Qualitäten: 10a; Sicherheitsklasse: -
 | H2 Ebene 0 | WI-LB | 1113Wa 0812441640 | yes |  | m² | Trockenbauarbeiten | Wand | Innenwand 1-Schalig | WI-LB |  |  | 0 | 1113HWa0812440884 |  |  |  | 0 |  |  | 0 | AllplanAttributes - Ortscode_Geschoßbezeichnung: E00; W_Deckenanschluss: Gleitender Deckenanschluss Fall 03; ash_W_Trockenbau_Qualitäten: 10a; Sicherheitsklasse: -
 | H2 Ebene 0 | WI-LB | 1113Wa 0812441691 | yes |  | m² | Trockenbauarbeiten | Wand | Innenwand 1-Schalig | WI-LB |  |  | 0 | 1113HWa0812440885 |  |  |  | 0 |  |  | 0 | AllplanAttributes - Ortscode_Geschoßbezeichnung: E00; W_Deckenanschluss: Gleitender Deckenanschluss Fall 03; ash_W_Trockenbau_Qualitäten: 10a; Sicherheitsklasse: -
 | H2 Ebene 0 | WI-LB | 1113Wa 0812441623 | yes |  | m² | Trockenbauarbeiten | Wand | Innenwand 1-Schalig | WI-LB |  |  | 0 | 1113HWa0812440881 | NEW |  |  | 0 |  |  | 0 | AllplanAttributes - W_Deckenanschluss: Gleitender Deckenanschluss Fall 03; ash_W_Trockenbau_Qualitäten: 1b; Sicherheitsklasse: -
 | H2 Ebene 0 | WI-LB | 1113Wa 0812944923 | yes |  | m² | Trockenbauarbeiten | Wand | Innenwand 1-Schalig | WI-LB |  |  | 0 | 1113HWa0812944921 | NEW |  |  | 0 |  |  | 0 | AllplanAttributes - W_Deckenanschluss: Gleitender Deckenanschluss Fall 03; ash_W_Trockenbau_Qualitäten: 1b; Sicherheitsklasse: -
 | H2 Ebene 0 | WI-LB | 1113Wa 0812441637 | yes |  | m² | Trockenbauarbeiten | Wand | Innenwand 1-Schalig | WI-LB |  |  | 0 | 1113HWa0812440898 |  |  |  | 0 |  |  | 0 | AllplanAttributes - Ortscode_Geschoßbezeichnung: E00; W_Deckenanschluss: Gleitender Deckenanschluss Fall 03; ash_W_Trockenbau_Qualitäten: 10a; Sicherheitsklasse: -
 | H2 Ebene 0 | WI-LB | 1113Wa 0812441666 | yes |  | m² | Trockenbauarbeiten | Wand | Innenwand 1-Schalig | WI-LB |  |  | 0 | 1113HWa0812440899 |  |  |  | 0 |  |  | 0 | AllplanAttributes - Ortscode_Geschoßbezeichnung: E00; W_Deckenanschluss: Gleitender Deckenanschluss Fall 03; ash_W_Trockenbau_Qualitäten: 10a; Sicherheitsklasse: -
 | H2 Ebene 0 | WI-LB | 1113Wa 0812441658 | yes |  | m² | Trockenbauarbeiten | Wand | Innenwand 1-Schalig | WI-LB |  |  | 0 | 1113HWa0812440934 |  |  |  | 0 |  |  | 47 | AllplanAttributes - Ortscode_Geschoßbezeichnung: E00; W_Deckenanschluss: Gleitender Deckenanschluss Fall 03; ash_W_Trockenbau_Qualitäten: 1c; Sicherheitsklasse: -
 | H2 Ebene 0 | WI-LB | 1113Wa 0812441694 | yes |  | m² | Trockenbauarbeiten | Wand | Innenwand 1-Schalig | WI-LB |  |  | 0 | 1113HWa0812440900 |  |  |  | 0 |  |  | 0 | AllplanAttributes - Ortscode_Geschoßbezeichnung: E00; W_Deckenanschluss: Gleitender Deckenanschluss Fall 03; ash_W_Trockenbau_Qualitäten: 10a; Sicherheitsklasse: -
 | H2 Ebene 0 | WI-LB | 1113Wa 0812441648 | yes |  | m² | Trockenbauarbeiten | Wand | Innenwand 1-Schalig | WI-LB |  |  | 0 | 1113HWa0812440928 |  |  |  | 0 |  |  | 47 | AllplanAttributes - Ortscode_Geschoßbezeichnung: E00; W_Deckenanschluss: Gleitender Deckenanschluss Fall 03; ash_W_Trockenbau_Qualitäten: 1c; Sicherheitsklasse: -
 | H2 Ebene 0 | WI-LB | 1113Wa 0812441625 | yes |  | m² | Trockenbauarbeiten | Wand | Innenwand 1-Schalig | WI-LB |  |  | 0 | 1113HWa0812440879 | NEW |  |  | 0 |  |  | 0 | AllplanAttributes - W_Deckenanschluss: Gleitender Deckenanschluss Fall 03; ash_W_Trockenbau_Qualitäten: 1b; Sicherheitsklasse: -
WV 1.1 | H2 Ebene 0 |  | 1113Sma0814159578 |  | VUK1 - Lichtleiste (ELT) | St | Trockenbauarbeiten | SmartPart | WV 1.1 |  |  |  | 0.2 |  |  |  |  | - | AllplanAttributes - W_Deckenanschluss: Gleitender Deckenanschluss Fall 02; Text1: WA; UK: 0 m; OK: 0 m; V6: 0 m; V7: 0 m; V8: 0 m; V9: 0; Länge: 1.2 m; Dicke: 0.025 m; Höhe: 0.15 m; Programmversion: 3.1; Text3: 0; Plugin_Bezeichnung: MainObject; Plugin_Objektname: SmartPartCompressed; Version: 1.1; Abstand_Öffn_Unten: 1.625 m; ash T_Feuchtebeständigkeit: nein; Feuerwiderstandsklasse~: nein
WV 1.1 | H2 Ebene 0 |  | 1113Sma0814159592 |  | VUK1 - Lichtleiste (ELT) | St | Trockenbauarbeiten | SmartPart | WV 1.1 |  |  |  | 0.2 |  |  |  |  | - | AllplanAttributes - W_Deckenanschluss: Gleitender Deckenanschluss Fall 02; Text1: WA2003; UK: 0 m; OK: 0 m; V6: 0 m; V7: 0 m; V8: 0 m; V9: 0; Länge: 1.2 m; Dicke: 0.025 m; Höhe: 0.15 m; Programmversion: 3.1; Text3: 0; Plugin_Bezeichnung: MainObject; Plugin_Objektname: SmartPartCompressed; Version: 1.1; Abstand_Öffn_Unten: 1.625 m; ash T_Feuchtebeständigkeit: nein; Feuerwiderstandsklasse~: nein
WV 1.1 | H2 Ebene 0 |  | 1113Sma0814159605 |  | VUK1 - Lichtleiste (ELT) | St | Trockenbauarbeiten | SmartPart | WV 1.1 |  |  |  | 0.2 |  |  |  |  | - | AllplanAttributes - W_Deckenanschluss: Gleitender Deckenanschluss Fall 02; Text1: WA2003; UK: 0 m; OK: 0 m; V6: 0 m; V7: 0 m; V8: 0 m; V9: 0; Länge: 1.2 m; Dicke: 0.025 m; Höhe: 0.15 m; Programmversion: 3.1; Text3: 0; Plugin_Bezeichnung: MainObject; Plugin_Objektname: SmartPartCompressed; Version: 1.1; Abstand_Öffn_Unten: 1.625 m; ash T_Feuchtebeständigkeit: nein; Feuerwiderstandsklasse~: nein
WV 1.1 | H2 Ebene 0 |  | 1113Sma0814159619 |  | VUK1 - Lichtleiste (ELT) | St | Trockenbauarbeiten | SmartPart | WV 1.1 |  |  |  | 0.2 |  |  |  |  | - | AllplanAttributes - W_Deckenanschluss: Gleitender Deckenanschluss Fall 02; Text1: WA2004; UK: 0 m; OK: 0 m; V6: 0 m; V7: 0 m; V8: 0 m; V9: 0; Länge: 1.2 m; Dicke: 0.025 m; Höhe: 0.15 m; Programmversion: 3.1; Text3: 0; Plugin_Bezeichnung: MainObject; Plugin_Objektname: SmartPartCompressed; Version: 1.1; Abstand_Öffn_Unten: 1.625 m; ash T_Feuchtebeständigkeit: nein; Feuerwiderstandsklasse~: nein
WV 1.1 | H2 Ebene 0 |  | 1113Sma0814159632 |  | VUK1 - Lichtleiste (ELT) | St | Trockenbauarbeiten | SmartPart | WV 1.1 |  |  |  | 0.2 |  |  |  |  | - | AllplanAttributes - W_Deckenanschluss: Gleitender Deckenanschluss Fall 02; Text1: WA2004; UK: 0 m; OK: 0 m; V6: 0 m; V7: 0 m; V8: 0 m; V9: 0; Länge: 1.2 m; Dicke: 0.025 m; Höhe: 0.15 m; Programmversion: 3.1; Text3: 0; Plugin_Bezeichnung: MainObject; Plugin_Objektname: SmartPartCompressed; Version: 1.1; Abstand_Öffn_Unten: 1.625 m; ash T_Feuchtebeständigkeit: nein; Feuerwiderstandsklasse~: nein
WV 1.1 | H2 Ebene 0 |  | 1113Sma0814159646 |  | VUK1 - Lichtleiste (ELT) | St | Trockenbauarbeiten | SmartPart | WV 1.1 |  |  |  | 0.2 |  |  |  |  | - | AllplanAttributes - W_Deckenanschluss: Gleitender Deckenanschluss Fall 02; Text1: WA2002; UK: 0 m; OK: 0 m; V6: 0 m; V7: 0 m; V8: 0 m; V9: 0; Länge: 1.2 m; Dicke: 0.025 m; Höhe: 0.15 m; Programmversion: 3.1; Text3: 0; Plugin_Bezeichnung: MainObject; Plugin_Objektname: SmartPartCompressed; Version: 1.1; Abstand_Öffn_Unten: 1.625 m; ash T_Feuchtebeständigkeit: nein; Feuerwiderstandsklasse~: nein
WV 1.1 | H2 Ebene 0 |  | 1113Sma0814159664 |  | VUK1 - Lichtleiste (ELT) | St | Trockenbauarbeiten | SmartPart | WV 1.1 |  |  |  | 0.2 |  |  |  |  | - | AllplanAttributes - W_Deckenanschluss: Gleitender Deckenanschluss Fall 02; Text1: WA2001; UK: 0 m; OK: 0 m; V6: 0 m; V7: 0 m; V8: 0 m; V9: 0; Länge: 1.2 m; Dicke: 0.025 m; Höhe: 0.15 m; Programmversion: 3.1; Text3: 0; Plugin_Bezeichnung: MainObject; Plugin_Objektname: SmartPartCompressed; Version: 1.1; Abstand_Öffn_Unten: 1.625 m; ash T_Feuchtebeständigkeit: nein; Feuerwiderstandsklasse~: nein
WV 1.1 | H2 Ebene 0 |  | 1113Sma0814159677 |  | VUK1 - Lichtleiste (ELT) | St | Trockenbauarbeiten | SmartPart | WV 1.1 |  |  |  | 0.2 |  |  |  |  | - | AllplanAttributes - W_Deckenanschluss: Gleitender Deckenanschluss Fall 02; Text1: WA2001; UK: 0 m; OK: 0 m; V6: 0 m; V7: 0 m; V8: 0 m; V9: 0; Länge: 1.2 m; Dicke: 0.025 m; Höhe: 0.15 m; Programmversion: 3.1; Text3: 0; Plugin_Bezeichnung: MainObject; Plugin_Objektname: SmartPartCompressed; Version: 1.1; Abstand_Öffn_Unten: 1.625 m; ash T_Feuchtebeständigkeit: nein; Feuerwiderstandsklasse~: nein
WV 1.1 | H2 Ebene 0 |  | 1113Sma0814159691 |  | VUK1 - Lichtleiste (ELT) | St | Trockenbauarbeiten | SmartPart | WV 1.1 |  |  |  | 0.2 |  |  |  |  | - | AllplanAttributes - W_Deckenanschluss: Gleitender Deckenanschluss Fall 02; Text1: WA2010; UK: 0 m; OK: 0 m; V6: 0 m; V7: 0 m; V8: 0 m; V9: 0; Länge: 1.2 m; Dicke: 0.025 m; Höhe: 0.15 m; Programmversion: 3.1; Text3: 0; Plugin_Bezeichnung: MainObject; Plugin_Objektname: SmartPartCompressed; Version: 1.1; Abstand_Öffn_Unten: 1.625 m; ash T_Feuchtebeständigkeit: nein; Feuerwiderstandsklasse~: nein
WV 1.1 | H2 Ebene 0 |  | 1113Sma0814159704 |  | VUK1 - Lichtleiste (ELT) | St | Trockenbauarbeiten | SmartPart | WV 1.1 |  |  |  | 0.2 |  |  |  |  | - | AllplanAttributes - W_Deckenanschluss: Gleitender Deckenanschluss Fall 02; Text1: WA2010; UK: 0 m; OK: 0 m; V6: 0 m; V7: 0 m; V8: 0 m; V9: 0; Länge: 1.2 m; Dicke: 0.025 m; Höhe: 0.15 m; Programmversion: 3.1; Text3: 0; Plugin_Bezeichnung: MainObject; Plugin_Objektname: SmartPartCompressed; Version: 1.1; Abstand_Öffn_Unten: 1.625 m; ash T_Feuchtebeständigkeit: nein; Feuerwiderstandsklasse~: nein
 | H2 Ebene 0 | WI-LB | 1113Wa 0812532030 | yes |  | m² | Trockenbauarbeiten | Wand | Innenwand 1-Schalig | WI-LB |  |  | 0 | 1113HWa0812532027 |  |  |  | 0 |  |  | 42 | AllplanAttributes - Ortscode_Geschoßbezeichnung: E00; W_Deckenanschluss: Gleitender Deckenanschluss Fall 03; ash_W_Trockenbau_Qualitäten: 1b; Sicherheitsklasse: -
 | H2 Ebene 0 | WI-LB | 1113Wa 0812441621 | yes |  | m² | Trockenbauarbeiten | Wand | Innenwand 1-Schalig | WI-LB |  |  | 0 | 1113HWa0812440877 | NEW |  |  | 0 |  |  | 0 | AllplanAttributes - W_Deckenanschluss: Gleitender Deckenanschluss Fall 03; ash_W_Trockenbau_Qualitäten: 1b; Sicherheitsklasse: -
 | H2 Ebene 0 | WI-IW | 1113Wa 0812467431 | yes |  | m² | Trockenbauarbeiten | Wand | Installationswand | WI-IW |  |  | 0 | 1113HWa0812467422 | NEW |  |  | 0 |  |  | 0 | AllplanAttributes - W_Deckenanschluss: Gleitender Deckenanschluss Fall 03; ash_W_Trockenbau_Qualitäten: 2; Sicherheitsklasse: -
 | H2 Ebene 0 | Installationsraum | 1113Wa 0812467430 | yes |  | m² | Trockenbauarbeiten | Wand | Installationswand | Installationsraum |  |  | 0 | 1113HWa0812467422 | NEW |  |  | 0 |  |  | 0 | AllplanAttributes - Sicherheitsklasse: -
 | H2 Ebene 0 | WI-IW | 1113Wa 0814135911 | yes |  | m² | Trockenbauarbeiten | Wand | Installationswand | WI-IW |  |  | 0 | 1113HWa0814135910 | NEW |  |  | 0 |  |  | 0 | AllplanAttributes - W_Deckenanschluss: Gleitender Deckenanschluss Fall 03; ash_W_Trockenbau_Qualitäten: 2; Sicherheitsklasse: -
 | H2 Ebene 0 | Installationsraum | 1113Wa 0814135912 | yes |  | m² | Trockenbauarbeiten | Wand | Installationswand | Installationsraum |  |  | 0 | 1113HWa0814135910 | NEW |  |  | 0 |  |  | 0 | AllplanAttributes - Sicherheitsklasse: -
 | H2 Ebene 0 | WI-IW | 1113Wa 0814134135 | yes |  | m² | Trockenbauarbeiten | Wand | Installationswand | WI-IW |  |  | 0 | 1113HWa0814134134 | NEW |  |  | 0 |  |  | 0 | AllplanAttributes - W_Deckenanschluss: Gleitender Deckenanschluss Fall 03; ash_W_Trockenbau_Qualitäten: 2; Sicherheitsklasse: -
 | H2 Ebene 0 | Installationsraum | 1113Wa 0814134136 | yes |  | m² | Trockenbauarbeiten | Wand | Installationswand | Installationsraum |  |  | 0 | 1113HWa0814134134 | NEW |  |  | 0 |  |  | 0 | AllplanAttributes - Sicherheitsklasse: -
 | H2 Ebene 0 | WI-IW | 1113Wa 0814134152 | yes |  | m² | Trockenbauarbeiten | Wand | Installationswand | WI-IW |  |  | 0 | 1113HWa0814134151 | NEW |  |  | 0 |  |  | 0 | AllplanAttributes - W_Deckenanschluss: Gleitender Deckenanschluss Fall 03; ash_W_Trockenbau_Qualitäten: 2; Sicherheitsklasse: -
 | H2 Ebene 0 | Installationsraum | 1113Wa 0814134153 | yes |  | m² | Trockenbauarbeiten | Wand | Installationswand | Installationsraum |  |  | 0 | 1113HWa0814134151 | NEW |  |  | 0 |  |  | 0 | AllplanAttributes - Sicherheitsklasse: -
 | H2 Ebene 0 | WI-IW | 1113Wa 0814134372 | yes |  | m² | Trockenbauarbeiten | Wand | Installationswand | WI-IW |  |  | 0 | 1113HWa0814134371 | NEW |  |  | 0 |  |  | 0 | AllplanAttributes - W_Deckenanschluss: Gleitender Deckenanschluss Fall 03; ash_W_Trockenbau_Qualitäten: 2; Sicherheitsklasse: -
 | H2 Ebene 0 | Installationsraum | 1113Wa 0814134373 | yes |  | m² | Trockenbauarbeiten | Wand | Installationswand | Installationsraum |  |  | 0 | 1113HWa0814134371 | NEW |  |  | 0 |  |  | 0 | AllplanAttributes - Sicherheitsklasse: -
 | H2 Ebene 0 | WI-IW | 1113Wa 0814134389 | yes |  | m² | Trockenbauarbeiten | Wand | Installationswand | WI-IW |  |  | 0 | 1113HWa0814134388 | NEW |  |  | 0 |  |  | 0 | AllplanAttributes - W_Deckenanschluss: Gleitender Deckenanschluss Fall 03; ash_W_Trockenbau_Qualitäten: 2; Sicherheitsklasse: -
 | H2 Ebene 0 | Installationsraum | 1113Wa 0814134390 | yes |  | m² | Trockenbauarbeiten | Wand | Installationswand | Installationsraum |  |  | 0 | 1113HWa0814134388 | NEW |  |  | 0 |  |  | 0 | AllplanAttributes - Sicherheitsklasse: -
 | H2 Ebene 0 | WI-IW | 1113Wa 0812441864 | yes |  | m² | Trockenbauarbeiten | Wand | Installationswand | WI-IW |  |  | 0 | 1113HWa0812441856 | NEW |  |  | 0 |  |  | 0 | AllplanAttributes - W_Deckenanschluss: Gleitender Deckenanschluss Fall 03; ash_W_Trockenbau_Qualitäten: 2; Sicherheitsklasse: -
 | H2 Ebene 0 | Installationsraum | 1113Wa 0812442497 | yes |  | m² | Trockenbauarbeiten | Wand | Installationswand | Installationsraum |  |  | 0 | 1113HWa0812441856 | NEW |  |  | 0 |  |  | 0 | AllplanAttributes - Sicherheitsklasse: -
 | H2 Ebene 0 | WI-IW | 1113Wa 0812467432 | yes |  | m² | Trockenbauarbeiten | Wand | Installationswand | WI-IW |  |  | 0 | 1113HWa0812467424 | NEW |  |  | 0 |  |  | 47 | AllplanAttributes - W_Deckenanschluss: Gleitender Deckenanschluss Fall 03; ash_W_Trockenbau_Qualitäten: 11; Sicherheitsklasse: -
 | H2 Ebene 0 | Installationsraum | 1113Wa 0812467439 | yes |  | m² | Trockenbauarbeiten | Wand | Installationswand | Installationsraum |  |  | 0 | 1113HWa0812467424 | NEW |  |  | 0 |  |  | 0 | AllplanAttributes - Sicherheitsklasse: -
 | H2 Ebene 0 | WI-IW | 1113Wa 0812467438 | yes |  | m² | Trockenbauarbeiten | Wand | Installationswand | WI-IW |  |  | 0 | 1113HWa0812467424 | NEW |  |  | 0 |  |  | 47 | AllplanAttributes - W_Deckenanschluss: Gleitender Deckenanschluss Fall 03; ash_W_Trockenbau_Qualitäten: 11; Sicherheitsklasse: -
 | H2 Ebene 0 | WI-IW | 1113Wa 0814134121 | yes |  | m² | Trockenbauarbeiten | Wand | Installationswand | WI-IW |  |  | 0 | 1113HWa0814134117 | NEW |  |  | 0 |  |  | 47 | AllplanAttributes - W_Deckenanschluss: Gleitender Deckenanschluss Fall 03; ash_W_Trockenbau_Qualitäten: 11; Sicherheitsklasse: -
 | H2 Ebene 0 | Installationsraum | 1113Wa 0814134120 | yes |  | m² | Trockenbauarbeiten | Wand | Installationswand | Installationsraum |  |  | 0 | 1113HWa0814134117 | NEW |  |  | 0 |  |  | 0 | AllplanAttributes - Sicherheitsklasse: -
 | H2 Ebene 0 | WI-IW | 1113Wa 0814134119 | yes |  | m² | Trockenbauarbeiten | Wand | Installationswand | WI-IW |  |  | 0 | 1113HWa0814134117 | NEW |  |  | 0 |  |  | 47 | AllplanAttributes - W_Deckenanschluss: Gleitender Deckenanschluss Fall 03; ash_W_Trockenbau_Qualitäten: 11; Sicherheitsklasse: -
 | H2 Ebene 0 | WI-IW | 1113Wa 0814134347 | yes |  | m² | Trockenbauarbeiten | Wand | Installationswand | WI-IW |  |  | 0 | 1113HWa0814134346 | NEW |  |  | 0 |  |  | 47 | AllplanAttributes - W_Deckenanschluss: Gleitender Deckenanschluss Fall 03; ash_W_Trockenbau_Qualitäten: 11; Sicherheitsklasse: -
 | H2 Ebene 0 | Installationsraum | 1113Wa 0814134348 | yes |  | m² | Trockenbauarbeiten | Wand | Installationswand | Installationsraum |  |  | 0 | 1113HWa0814134346 | NEW |  |  | 0 |  |  | 0 | AllplanAttributes - Sicherheitsklasse: -
 | H2 Ebene 0 | WI-IW | 1113Wa 0814134349 | yes |  | m² | Trockenbauarbeiten | Wand | Installationswand | WI-IW |  |  | 0 | 1113HWa0814134346 | NEW |  |  | 0 |  |  | 47 | AllplanAttributes - W_Deckenanschluss: Gleitender Deckenanschluss Fall 03; ash_W_Trockenbau_Qualitäten: 11; Sicherheitsklasse: -
 | H2 Ebene 0 | WI-IW | 1113Wa 0812441866 | yes |  | m² | Trockenbauarbeiten | Wand | Installationswand | WI-IW |  |  | 0 | 1113HWa0812441858 | NEW |  |  | 0 |  |  | 0 | AllplanAttributes - W_Deckenanschluss: Gleitender Deckenanschluss Fall 03; ash_W_Trockenbau_Qualitäten: 2; Sicherheitsklasse: -
 | H2 Ebene 0 | Installationsraum | 1113Wa 0812442495 | yes |  | m² | Trockenbauarbeiten | Wand | Installationswand | Installationsraum |  |  | 0 | 1113HWa0812441858 | NEW |  |  | 0 |  |  | 0 | AllplanAttributes - Sicherheitsklasse: -
 | H2 Ebene 0 | WI-IW | 1113Wa 0814135794 | yes |  | m² | Trockenbauarbeiten | Wand | Installationswand | WI-IW |  |  | 0 | 1113HWa0814135793 | NEW |  |  | 0 |  |  | 0 | AllplanAttributes - W_Deckenanschluss: Gleitender Deckenanschluss Fall 03; ash_W_Trockenbau_Qualitäten: 2; Sicherheitsklasse: -
 | H2 Ebene 0 | Installationsraum | 1113Wa 0814135795 | yes |  | m² | Trockenbauarbeiten | Wand | Installationswand | Installationsraum |  |  | 0 | 1113HWa0814135793 | NEW |  |  | 0 |  |  | 0 | AllplanAttributes - Sicherheitsklasse: -
 | H2 Ebene 0 | WI-IW | 1113Wa 0814135769 | yes |  | m² | Trockenbauarbeiten | Wand | Installationswand | WI-IW |  |  | 0 | 1113HWa0814135768 | NEW |  |  | 0 |  |  | 47 | AllplanAttributes - W_Deckenanschluss: Gleitender Deckenanschluss Fall 03; ash_W_Trockenbau_Qualitäten: 11; Sicherheitsklasse: -
 | H2 Ebene 0 | Installationsraum | 1113Wa 0814135770 | yes |  | m² | Trockenbauarbeiten | Wand | Installationswand | Installationsraum |  |  | 0 | 1113HWa0814135768 | NEW |  |  | 0 |  |  | 0 | AllplanAttributes - Sicherheitsklasse: -
 | H2 Ebene 0 | WI-IW | 1113Wa 0814135771 | yes |  | m² | Trockenbauarbeiten | Wand | Installationswand | WI-IW |  |  | 0 | 1113HWa0814135768 | NEW |  |  | 0 |  |  | 47 | AllplanAttributes - W_Deckenanschluss: Gleitender Deckenanschluss Fall 03; ash_W_Trockenbau_Qualitäten: 11; Sicherheitsklasse: -
 | H2 Ebene 0 | WI-IW | 1113Wa 0814135931 | yes |  | m² | Trockenbauarbeiten | Wand | Installationswand | WI-IW |  |  | 0 | 1113HWa0814135930 | NEW |  |  | 0 |  |  | 0 | AllplanAttributes - W_Deckenanschluss: Gleitender Deckenanschluss Fall 03; ash_W_Trockenbau_Qualitäten: 2; Sicherheitsklasse: -
 | H2 Ebene 0 | Installationsraum | 1113Wa 0814135932 | yes |  | m² | Trockenbauarbeiten | Wand | Installationswand | Installationsraum |  |  | 0 | 1113HWa0814135930 | NEW |  |  | 0 |  |  | 0 | AllplanAttributes - Sicherheitsklasse: -
 | H2 Ebene 0 | WI-IW | 1113Wa 0814136000 | yes |  | m² | Trockenbauarbeiten | Wand | Installationswand | WI-IW |  |  | 0 | 1113HWa0814135999 | NEW |  |  | 0 |  |  | 0 | AllplanAttributes - W_Deckenanschluss: Gleitender Deckenanschluss Fall 03; ash_W_Trockenbau_Qualitäten: 2; Sicherheitsklasse: -
 | H2 Ebene 0 | Installationsraum | 1113Wa 0814136001 | yes |  | m² | Trockenbauarbeiten | Wand | Installationswand | Installationsraum |  |  | 0 | 1113HWa0814135999 | NEW |  |  | 0 |  |  | 0 | AllplanAttributes - Sicherheitsklasse: -
 | H2 Ebene 0 | WI-IW | 1113Wa 0814135975 | yes |  | m² | Trockenbauarbeiten | Wand | Installationswand | WI-IW |  |  | 0 | 1113HWa0814135974 | NEW |  |  | 0 |  |  | 47 | AllplanAttributes - W_Deckenanschluss: Gleitender Deckenanschluss Fall 03; ash_W_Trockenbau_Qualitäten: 11; Sicherheitsklasse: -
 | H2 Ebene 0 | Installationsraum | 1113Wa 0814135976 | yes |  | m² | Trockenbauarbeiten | Wand | Installationswand | Installationsraum |  |  | 0 | 1113HWa0814135974 | NEW |  |  | 0 |  |  | 0 | AllplanAttributes - Sicherheitsklasse: -
 | H2 Ebene 0 | WI-IW | 1113Wa 0814135977 | yes |  | m² | Trockenbauarbeiten | Wand | Installationswand | WI-IW |  |  | 0 | 1113HWa0814135974 | NEW |  |  | 0 |  |  | 47 | AllplanAttributes - W_Deckenanschluss: Gleitender Deckenanschluss Fall 03; ash_W_Trockenbau_Qualitäten: 11; Sicherheitsklasse: -
 | H2 Ebene 0 | WI-IW | 1113Wa 0814136017 | yes |  | m² | Trockenbauarbeiten | Wand | Installationswand | WI-IW |  |  | 0 | 1113HWa0814136016 | NEW |  |  | 0 |  |  | 0 | AllplanAttributes - W_Deckenanschluss: Gleitender Deckenanschluss Fall 03; ash_W_Trockenbau_Qualitäten: 2; Sicherheitsklasse: -
 | H2 Ebene 0 | Installationsraum | 1113Wa 0814136018 | yes |  | m² | Trockenbauarbeiten | Wand | Installationswand | Installationsraum |  |  | 0 | 1113HWa0814136016 | NEW |  |  | 0 |  |  | 0 | AllplanAttributes - Sicherheitsklasse: -
 | H2 Ebene 0 | WI-IW | 1113Wa 0814136079 | yes |  | m² | Trockenbauarbeiten | Wand | Installationswand | WI-IW |  |  | 0 | 1113HWa0814136078 | NEW |  |  | 0 |  |  | 0 | AllplanAttributes - W_Deckenanschluss: Gleitender Deckenanschluss Fall 03; ash_W_Trockenbau_Qualitäten: 2; Sicherheitsklasse: -
 | H2 Ebene 0 | Installationsraum | 1113Wa 0814136080 | yes |  | m² | Trockenbauarbeiten | Wand | Installationswand | Installationsraum |  |  | 0 | 1113HWa0814136078 | NEW |  |  | 0 |  |  | 0 | AllplanAttributes - Sicherheitsklasse: -
 | H2 Ebene 0 | WI-IW | 1113Wa 0814136054 | yes |  | m² | Trockenbauarbeiten | Wand | Installationswand | WI-IW |  |  | 0 | 1113HWa0814136053 | NEW |  |  | 0 |  |  | 47 | AllplanAttributes - W_Deckenanschluss: Gleitender Deckenanschluss Fall 03; ash_W_Trockenbau_Qualitäten: 11; Sicherheitsklasse: -
 | H2 Ebene 0 | Installationsraum | 1113Wa 0814136055 | yes |  | m² | Trockenbauarbeiten | Wand | Installationswand | Installationsraum |  |  | 0 | 1113HWa0814136053 | NEW |  |  | 0 |  |  | 0 | AllplanAttributes - Sicherheitsklasse: -
 | H2 Ebene 0 | WI-IW | 1113Wa 0814136056 | yes |  | m² | Trockenbauarbeiten | Wand | Installationswand | WI-IW |  |  | 0 | 1113HWa0814136053 | NEW |  |  | 0 |  |  | 47 | AllplanAttributes - W_Deckenanschluss: Gleitender Deckenanschluss Fall 03; ash_W_Trockenbau_Qualitäten: 11; Sicherheitsklasse: -
 | H2 Ebene 0 | WI-IW | 1113Wa 0814136096 | yes |  | m² | Trockenbauarbeiten | Wand | Installationswand | WI-IW |  |  | 0 | 1113HWa0814136095 | NEW |  |  | 0 |  |  | 0 | AllplanAttributes - W_Deckenanschluss: Gleitender Deckenanschluss Fall 03; ash_W_Trockenbau_Qualitäten: 2; Sicherheitsklasse: -
 | H2 Ebene 0 | Installationsraum | 1113Wa 0814136097 | yes |  | m² | Trockenbauarbeiten | Wand | Installationswand | Installationsraum |  |  | 0 | 1113HWa0814136095 | NEW |  |  | 0 |  |  | 0 | AllplanAttributes - Sicherheitsklasse: -
 | H2 Ebene 0 | WI-IW | 1113Wa 0814136130 | yes |  | m² | Trockenbauarbeiten | Wand | Installationswand | WI-IW |  |  | 0 | 1113HWa0814136129 | NEW |  |  | 0 |  |  | 0 | AllplanAttributes - W_Deckenanschluss: Gleitender Deckenanschluss Fall 03; ash_W_Trockenbau_Qualitäten: 2; Sicherheitsklasse: -
 | H2 Ebene 0 | Installationsraum | 1113Wa 0814136131 | yes |  | m² | Trockenbauarbeiten | Wand | Installationswand | Installationsraum |  |  | 0 | 1113HWa0814136129 | NEW |  |  | 0 |  |  | 0 | AllplanAttributes - Sicherheitsklasse: -
 | H2 Ebene 0 | WI-IW | 1113Wa 0814136145 | yes |  | m² | Trockenbauarbeiten | Wand | Installationswand | WI-IW |  |  | 0 | 1113HWa0814136144 | NEW |  |  | 0 |  |  | 0 | AllplanAttributes - W_Deckenanschluss: Gleitender Deckenanschluss Fall 03; ash_W_Trockenbau_Qualitäten: 2; Sicherheitsklasse: -
 | H2 Ebene 0 | Installationsraum | 1113Wa 0814136146 | yes |  | m² | Trockenbauarbeiten | Wand | Installationswand | Installationsraum |  |  | 0 | 1113HWa0814136144 | NEW |  |  | 0 |  |  | 0 | AllplanAttributes - Sicherheitsklasse: -
 | H2 Ebene 0 | Installationsraum | 1113Wa 0812468632 | yes |  | m² | Trockenbauarbeiten | Wand | Installationswand | Installationsraum |  |  | 0 | 1113HWa0812468619 | NEW |  |  | 0 |  |  | 0 | AllplanAttributes - Sicherheitsklasse: -
 | H2 Ebene 0 | WI-VS | 1113Wa 0812468630 | yes |  | m² | Trockenbauarbeiten | Wand | Installationswand | WI-VS |  |  | 0 | 1113HWa0812468619 | NEW |  |  | 0 |  |  | 0 | AllplanAttributes - W_Deckenanschluss: Gleitender Deckenanschluss Fall 03; ash_W_Trockenbau_Qualitäten: 2; Sicherheitsklasse: -
 | H2 Ebene 0 | WI-IW | 1113Wa 0814136711 | yes |  | m² | Trockenbauarbeiten | Wand | Installationswand | WI-IW |  |  | 0 | 1113HWa0814136710 | NEW |  |  | 0 |  |  | 0 | AllplanAttributes - W_Deckenanschluss: Gleitender Deckenanschluss Fall 03; ash_W_Trockenbau_Qualitäten: 2; Sicherheitsklasse: -
 | H2 Ebene 0 | Installationsraum | 1113Wa 0814136712 | yes |  | m² | Trockenbauarbeiten | Wand | Installationswand | Installationsraum |  |  | 0 | 1113HWa0814136710 | NEW |  |  | 0 |  |  | 0 | AllplanAttributes - Sicherheitsklasse: -
 | H2 Ebene 0 | WI-IW | 1113Wa 0812467962 | yes |  | m² | Trockenbauarbeiten | Wand | Installationswand | WI-IW |  |  | 0 | 1113HWa0812467954 | NEW |  |  | 0 |  |  | 47 | AllplanAttributes - W_Deckenanschluss: Gleitender Deckenanschluss Fall 03; ash_W_Trockenbau_Qualitäten: 11; Sicherheitsklasse: -
 | H2 Ebene 0 | Installationsraum | 1113Wa 0812467969 | yes |  | m² | Trockenbauarbeiten | Wand | Installationswand | Installationsraum |  |  | 0 | 1113HWa0812467954 | NEW |  |  | 0 |  |  | 0 | AllplanAttributes - Sicherheitsklasse: -
 | H2 Ebene 0 | WI-IW | 1113Wa 0812467968 | yes |  | m² | Trockenbauarbeiten | Wand | Installationswand | WI-IW |  |  | 0 | 1113HWa0812467954 | NEW |  |  | 0 |  |  | 47 | AllplanAttributes - W_Deckenanschluss: Gleitender Deckenanschluss Fall 03; ash_W_Trockenbau_Qualitäten: 11; Sicherheitsklasse: -
 | H2 Ebene 0 | WI-IW | 1113Wa 0814136728 | yes |  | m² | Trockenbauarbeiten | Wand | Installationswand | WI-IW |  |  | 0 | 1113HWa0814136727 | NEW |  |  | 0 |  |  | 0 | AllplanAttributes - W_Deckenanschluss: Gleitender Deckenanschluss Fall 03; ash_W_Trockenbau_Qualitäten: 2; Sicherheitsklasse: -
 | H2 Ebene 0 | Installationsraum | 1113Wa 0814136729 | yes |  | m² | Trockenbauarbeiten | Wand | Installationswand | Installationsraum |  |  | 0 | 1113HWa0814136727 | NEW |  |  | 0 |  |  | 0 | AllplanAttributes - Sicherheitsklasse: -
 | H2 Ebene 0 | WI-IW | 1113Wa 0814139142 | yes |  | m² | Trockenbauarbeiten | Wand | Installationswand | WI-IW |  |  | 0 | 1113HWa0814139141 | NEW |  |  | 0 |  |  | 0 | AllplanAttributes - W_Deckenanschluss: Gleitender Deckenanschluss Fall 03; ash_W_Trockenbau_Qualitäten: 2; Sicherheitsklasse: -
 | H2 Ebene 0 | Installationsraum | 1113Wa 0814139143 | yes |  | m² | Trockenbauarbeiten | Wand | Installationswand | Installationsraum |  |  | 0 | 1113HWa0814139141 | NEW |  |  | 0 |  |  | 0 | AllplanAttributes - Sicherheitsklasse: -
 | H2 Ebene 0 | WI-IW | 1113Wa 0814136682 | yes |  | m² | Trockenbauarbeiten | Wand | Installationswand | WI-IW |  |  | 0 | 1113HWa0814136680 | NEW |  |  | 0 |  |  | 47 | AllplanAttributes - W_Deckenanschluss: Gleitender Deckenanschluss Fall 03; ash_W_Trockenbau_Qualitäten: 11; Sicherheitsklasse: -
 | H2 Ebene 0 | Installationsraum | 1113Wa 0814136681 | yes |  | m² | Trockenbauarbeiten | Wand | Installationswand | Installationsraum |  |  | 0 | 1113HWa0814136680 | NEW |  |  | 0 |  |  | 0 | AllplanAttributes - Sicherheitsklasse: -
 | H2 Ebene 0 | WI-IW | 1113Wa 0814136684 | yes |  | m² | Trockenbauarbeiten | Wand | Installationswand | WI-IW |  |  | 0 | 1113HWa0814136680 | NEW |  |  | 0 |  |  | 47 | AllplanAttributes - W_Deckenanschluss: Gleitender Deckenanschluss Fall 03; ash_W_Trockenbau_Qualitäten: 11; Sicherheitsklasse: -
 | H2 Ebene 0 | WI-IW | 1113Wa 0814139162 | yes |  | m² | Trockenbauarbeiten | Wand | Installationswand | WI-IW |  |  | 0 | 1113HWa0814139161 | NEW |  |  | 0 |  |  | 0 | AllplanAttributes - W_Deckenanschluss: Gleitender Deckenanschluss Fall 03; ash_W_Trockenbau_Qualitäten: 2; Sicherheitsklasse: -
 | H2 Ebene 0 | Installationsraum | 1113Wa 0814139163 | yes |  | m² | Trockenbauarbeiten | Wand | Installationswand | Installationsraum |  |  | 0 | 1113HWa0814139161 | NEW |  |  | 0 |  |  | 0 | AllplanAttributes - Sicherheitsklasse: -
 | H2 Ebene 0 | WI-IW | 1113Wa 0814139179 | yes |  | m² | Trockenbauarbeiten | Wand | Installationswand | WI-IW |  |  | 0 | 1113HWa0814139178 | NEW |  |  | 0 |  |  | 0 | AllplanAttributes - W_Deckenanschluss: Gleitender Deckenanschluss Fall 03; ash_W_Trockenbau_Qualitäten: 2; Sicherheitsklasse: -
 | H2 Ebene 0 | Installationsraum | 1113Wa 0814139180 | yes |  | m² | Trockenbauarbeiten | Wand | Installationswand | Installationsraum |  |  | 0 | 1113HWa0814139178 | NEW |  |  | 0 |  |  | 0 | AllplanAttributes - Sicherheitsklasse: -
 | H2 Ebene 0 | WI-IW | 1113Wa 0814136698 | yes |  | m² | Trockenbauarbeiten | Wand | Installationswand | WI-IW |  |  | 0 | 1113HWa0814136695 | NEW |  |  | 0 |  |  | 47 | AllplanAttributes - W_Deckenanschluss: Gleitender Deckenanschluss Fall 03; ash_W_Trockenbau_Qualitäten: 11; Sicherheitsklasse: -
 | H2 Ebene 0 | Installationsraum | 1113Wa 0814136699 | yes |  | m² | Trockenbauarbeiten | Wand | Installationswand | Installationsraum |  |  | 0 | 1113HWa0814136695 | NEW |  |  | 0 |  |  | 0 | AllplanAttributes - Sicherheitsklasse: -
 | H2 Ebene 0 | WI-IW | 1113Wa 0814136697 | yes |  | m² | Trockenbauarbeiten | Wand | Installationswand | WI-IW |  |  | 0 | 1113HWa0814136695 | NEW |  |  | 0 |  |  | 47 | AllplanAttributes - W_Deckenanschluss: Gleitender Deckenanschluss Fall 03; ash_W_Trockenbau_Qualitäten: 11; Sicherheitsklasse: -
 | H2 Ebene 0 | WI-IW | 1113Wa 0814143833 | yes |  | m² | Trockenbauarbeiten | Wand | Installationswand | WI-IW |  |  | 0 | 1113HWa0814143832 | NEW |  |  | 0 |  |  | 0 | AllplanAttributes - W_Deckenanschluss: Gleitender Deckenanschluss Fall 03; ash_W_Trockenbau_Qualitäten: 2; Sicherheitsklasse: -
 | H2 Ebene 0 | Installationsraum | 1113Wa 0814143834 | yes |  | m² | Trockenbauarbeiten | Wand | Installationswand | Installationsraum |  |  | 0 | 1113HWa0814143832 | NEW |  |  | 0 |  |  | 0 | AllplanAttributes - Sicherheitsklasse: -
 | H2 Ebene 0 | WI-IW | 1113Wa 0814143802 | yes |  | m² | Trockenbauarbeiten | Wand | Installationswand | WI-IW |  |  | 0 | 1113HWa0814143800 | NEW |  |  | 0 |  |  | 47 | AllplanAttributes - W_Deckenanschluss: Gleitender Deckenanschluss Fall 03; ash_W_Trockenbau_Qualitäten: 11; Sicherheitsklasse: -
 | H2 Ebene 0 | Installationsraum | 1113Wa 0814143801 | yes |  | m² | Trockenbauarbeiten | Wand | Installationswand | Installationsraum |  |  | 0 | 1113HWa0814143800 | NEW |  |  | 0 |  |  | 0 | AllplanAttributes - Sicherheitsklasse: -
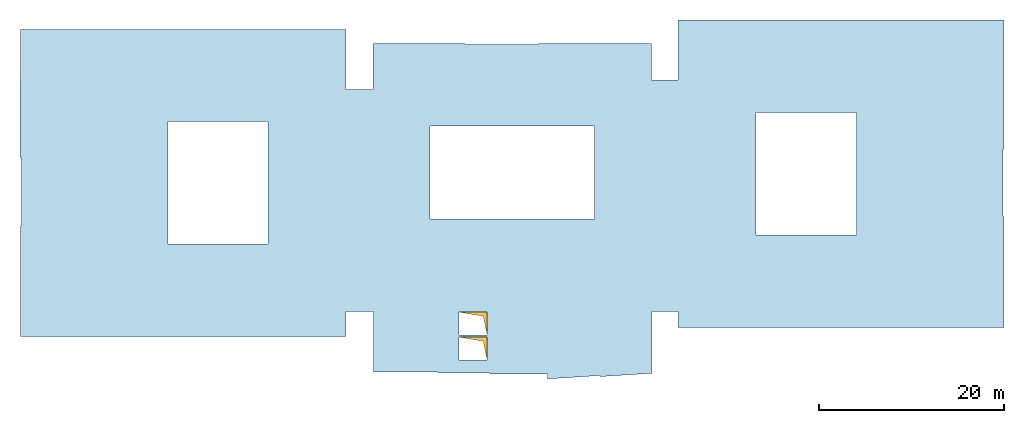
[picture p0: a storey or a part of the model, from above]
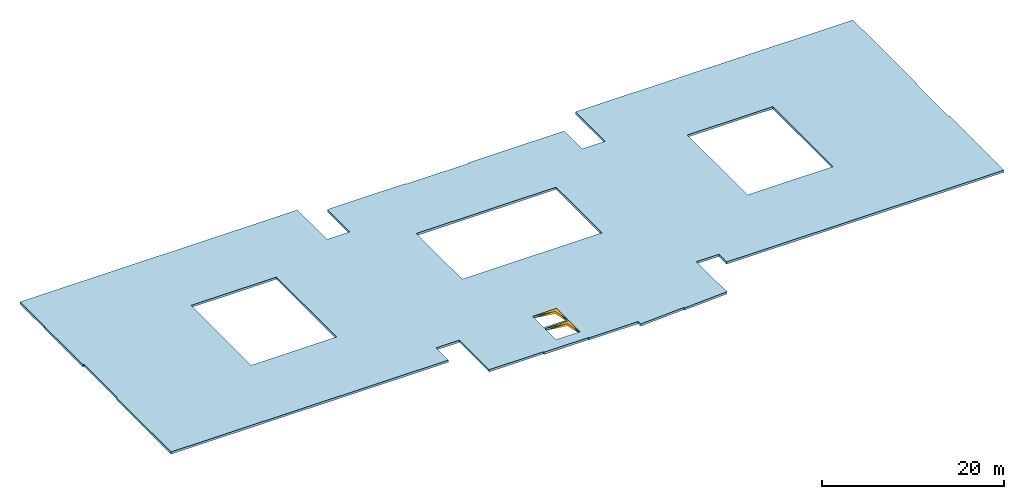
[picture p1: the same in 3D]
Properties of the parts of a building model (IFC4), part 77 of 80

# IfcWall (6826)
Name | In | Material | Allright_Bauteil_ID | 2D Interaktion | Codetext | Abrechnungsart | Gewerk | Objektname | Bezeichnung | AllplanAttributes, Material | Typ = SurfaceSpreadOfFlame | Brandschutzklasse | OKFF | P_ID | Status | LoadBearing | IsExternal | FireRating | ThermalTransmittance (W/K/m2) | Combustible | AcousticRating | Compartmentation | Reference
 | H2 Ebene 0 | WI-IW | 1113Wa 0814143804 | yes |  | m² | Trockenbauarbeiten | Wand | Installationswand | WI-IW |  |  | 0 | 1113HWa0814143800 | NEW |  |  | 0 |  |  | 47 | AllplanAttributes - W_Deckenanschluss: Gleitender Deckenanschluss Fall 03; ash_W_Trockenbau_Qualitäten: 11; Sicherheitsklasse: -
 | H2 Ebene 0 | WI-IW | 1113Wa 0814143816 | yes |  | m² | Trockenbauarbeiten | Wand | Installationswand | WI-IW |  |  | 0 | 1113HWa0814143815 | NEW |  |  | 0 |  |  | 0 | AllplanAttributes - W_Deckenanschluss: Gleitender Deckenanschluss Fall 03; ash_W_Trockenbau_Qualitäten: 2; Sicherheitsklasse: -
 | H2 Ebene 0 | Installationsraum | 1113Wa 0814143817 | yes |  | m² | Trockenbauarbeiten | Wand | Installationswand | Installationsraum |  |  | 0 | 1113HWa0814143815 | NEW |  |  | 0 |  |  | 0 | AllplanAttributes - Sicherheitsklasse: -
 | H2 Ebene 0 | WI-IW | 1113Wa 0814143784 | yes |  | m² | Trockenbauarbeiten | Wand | Installationswand | WI-IW |  |  | 0 | 1113HWa0814143783 | NEW |  |  | 0 |  |  | 0 | AllplanAttributes - W_Deckenanschluss: Gleitender Deckenanschluss Fall 03; ash_W_Trockenbau_Qualitäten: 2; Sicherheitsklasse: -
 | H2 Ebene 0 | Installationsraum | 1113Wa 0814143785 | yes |  | m² | Trockenbauarbeiten | Wand | Installationswand | Installationsraum |  |  | 0 | 1113HWa0814143783 | NEW |  |  | 0 |  |  | 0 | AllplanAttributes - Sicherheitsklasse: -
 | H2 Ebene 0 | WI-IW | 1113Wa 0814143753 | yes |  | m² | Trockenbauarbeiten | Wand | Installationswand | WI-IW |  |  | 0 | 1113HWa0814143751 | NEW |  |  | 0 |  |  | 47 | AllplanAttributes - W_Deckenanschluss: Gleitender Deckenanschluss Fall 03; ash_W_Trockenbau_Qualitäten: 11; Sicherheitsklasse: -
 | H2 Ebene 0 | Installationsraum | 1113Wa 0814143752 | yes |  | m² | Trockenbauarbeiten | Wand | Installationswand | Installationsraum |  |  | 0 | 1113HWa0814143751 | NEW |  |  | 0 |  |  | 0 | AllplanAttributes - Sicherheitsklasse: -
 | H2 Ebene 0 | WI-IW | 1113Wa 0814143755 | yes |  | m² | Trockenbauarbeiten | Wand | Installationswand | WI-IW |  |  | 0 | 1113HWa0814143751 | NEW |  |  | 0 |  |  | 47 | AllplanAttributes - W_Deckenanschluss: Gleitender Deckenanschluss Fall 03; ash_W_Trockenbau_Qualitäten: 11; Sicherheitsklasse: -
 | H2 Ebene 0 | WI-IW | 1113Wa 0814143767 | yes |  | m² | Trockenbauarbeiten | Wand | Installationswand | WI-IW |  |  | 0 | 1113HWa0814143766 | NEW |  |  | 0 |  |  | 0 | AllplanAttributes - W_Deckenanschluss: Gleitender Deckenanschluss Fall 03; ash_W_Trockenbau_Qualitäten: 2; Sicherheitsklasse: -
 | H2 Ebene 0 | Installationsraum | 1113Wa 0814143768 | yes |  | m² | Trockenbauarbeiten | Wand | Installationswand | Installationsraum |  |  | 0 | 1113HWa0814143766 | NEW |  |  | 0 |  |  | 0 | AllplanAttributes - Sicherheitsklasse: -
 | H2 Ebene 0 | WI-IW | 1113Wa 0814143735 | yes |  | m² | Trockenbauarbeiten | Wand | Installationswand | WI-IW |  |  | 0 | 1113HWa0814143734 | NEW |  |  | 0 |  |  | 0 | AllplanAttributes - W_Deckenanschluss: Gleitender Deckenanschluss Fall 03; ash_W_Trockenbau_Qualitäten: 2; Sicherheitsklasse: -
 | H2 Ebene 0 | Installationsraum | 1113Wa 0814143736 | yes |  | m² | Trockenbauarbeiten | Wand | Installationswand | Installationsraum |  |  | 0 | 1113HWa0814143734 | NEW |  |  | 0 |  |  | 0 | AllplanAttributes - Sicherheitsklasse: -
 | H2 Ebene 0 | WI-IW | 1113Wa 0814143673 | yes |  | m² | Trockenbauarbeiten | Wand | Installationswand | WI-IW |  |  | 0 | 1113HWa0814143672 | NEW |  |  | 0 |  |  | 47 | AllplanAttributes - W_Deckenanschluss: Gleitender Deckenanschluss Fall 03; ash_W_Trockenbau_Qualitäten: 11; Sicherheitsklasse: -
 | H2 Ebene 0 | Installationsraum | 1113Wa 0814143674 | yes |  | m² | Trockenbauarbeiten | Wand | Installationswand | Installationsraum |  |  | 0 | 1113HWa0814143672 | NEW |  |  | 0 |  |  | 0 | AllplanAttributes - Sicherheitsklasse: -
 | H2 Ebene 0 | WI-IW | 1113Wa 0814143675 | yes |  | m² | Trockenbauarbeiten | Wand | Installationswand | WI-IW |  |  | 0 | 1113HWa0814143672 | NEW |  |  | 0 |  |  | 47 | AllplanAttributes - W_Deckenanschluss: Gleitender Deckenanschluss Fall 03; ash_W_Trockenbau_Qualitäten: 11; Sicherheitsklasse: -
 | H2 Ebene 0 | WI-IW | 1113Wa 0814143718 | yes |  | m² | Trockenbauarbeiten | Wand | Installationswand | WI-IW |  |  | 0 | 1113HWa0814143717 | NEW |  |  | 0 |  |  | 0 | AllplanAttributes - W_Deckenanschluss: Gleitender Deckenanschluss Fall 03; ash_W_Trockenbau_Qualitäten: 2; Sicherheitsklasse: -
 | H2 Ebene 0 | Installationsraum | 1113Wa 0814143719 | yes |  | m² | Trockenbauarbeiten | Wand | Installationswand | Installationsraum |  |  | 0 | 1113HWa0814143717 | NEW |  |  | 0 |  |  | 0 | AllplanAttributes - Sicherheitsklasse: -
 | H2 Ebene 0 | Installationsraum | 1113Wa 0814154352 | yes |  | m² | Trockenbauarbeiten | Wand | Installationswand | Installationsraum |  |  | 0 | 1113HWa0814154351 | NEW |  |  | 0 |  |  | 0 | AllplanAttributes - Sicherheitsklasse: -
 | H2 Ebene 0 | WI-VS | 1113Wa 0814154353 | yes |  | m² | Trockenbauarbeiten | Wand | Installationswand | WI-VS |  |  | 0 | 1113HWa0814154351 | NEW |  |  | 0 |  |  | 0 | AllplanAttributes - W_Deckenanschluss: Gleitender Deckenanschluss Fall 03; ash_W_Trockenbau_Qualitäten: 2; Sicherheitsklasse: -
 | H2 Ebene 0 | Installationsraum | 1113Wa 0814154316 | yes |  | m² | Trockenbauarbeiten | Wand | Installationswand | Installationsraum |  |  | 0 | 1113HWa0814154315 | NEW |  |  | 0 |  |  | 0 | AllplanAttributes - Sicherheitsklasse: -
 | H2 Ebene 0 | WI-VS | 1113Wa 0814154317 | yes |  | m² | Trockenbauarbeiten | Wand | Installationswand | WI-VS |  |  | 0 | 1113HWa0814154315 | NEW |  |  | 0 |  |  | 0 | AllplanAttributes - W_Deckenanschluss: Gleitender Deckenanschluss Fall 03; ash_W_Trockenbau_Qualitäten: 2; Sicherheitsklasse: -
 | H2 Ebene 0 | WI-GKF | 1113Wa 0814251240 | yes |  | m² | Trockenbauarbeiten | Wand | Innenwand 1-Schalig | WI-GKF |  |  | 0 | 1113HWa0812812439 | NEW |  |  | 0 |  |  | 0 | AllplanAttributes - Sicherheitsklasse: -
 | H2 Ebene 0 | WI-HW 60 | 1113Wa 0814251241 | yes |  | m² | Zimmer- und Holzbauarbeiten | Wand | Innenwand 1-Schalig | WI-HW 60 |  |  | 0 | 1113HWa0813975950 | NEW |  |  | 0 | AllplanAttributes - Sicherheitsklasse: -
 | H2 Ebene 0 | WI-GKF | 1113Wa 0814251253 | yes |  | m² | Trockenbauarbeiten | Wand | Innenwand 1-Schalig | WI-GKF |  |  | 0 | 1113HWa0812812439 | NEW |  |  | 0 |  |  | 0 | AllplanAttributes - Sicherheitsklasse: -
 | H2 Ebene 0 | WI-HW 60 | 1113Wa 0814251254 | yes |  | m² | Zimmer- und Holzbauarbeiten | Wand | Innenwand 1-Schalig | WI-HW 60 |  |  | 0 | 1113HWa0813975950 | NEW |  |  | 0 | AllplanAttributes - Sicherheitsklasse: -
 | H2 Ebene 0 | WI-GKF | 1113Wa 0814251272 | yes |  | m² | Trockenbauarbeiten | Wand | Innenwand 1-Schalig | WI-GKF |  |  | 0 | 1113HWa0812812439 | NEW |  |  | 0 |  |  | 0 | AllplanAttributes - Sicherheitsklasse: -
 | H2 Ebene 0 | WI-HW 60 | 1113Wa 0814251273 | yes |  | m² | Zimmer- und Holzbauarbeiten | Wand | Innenwand 1-Schalig | WI-HW 60 |  |  | 0 | 1113HWa0813975950 | NEW |  |  | 0 | AllplanAttributes - Sicherheitsklasse: -
 | H2 Ebene 0 | WI-GKF | 1113Wa 0814251384 | yes |  | m² | Trockenbauarbeiten | Wand | Innenwand 1-Schalig | WI-GKF |  |  | 0 | 1113HWa0812812439 | NEW |  |  | 0 |  |  | 0 | AllplanAttributes - Sicherheitsklasse: -
 | H2 Ebene 0 | WI-HW 60 | 1113Wa 0814251385 | yes |  | m² | Zimmer- und Holzbauarbeiten | Wand | Innenwand 1-Schalig | WI-HW 60 |  |  | 0 | 1113HWa0813975950 | NEW |  |  | 0 | AllplanAttributes - Sicherheitsklasse: -
 | H2 Ebene 0 | WI-GKF | 1113Wa 0814251392 | yes |  | m² | Trockenbauarbeiten | Wand | Innenwand 1-Schalig | WI-GKF |  |  | 0 | 1113HWa0812812439 | NEW |  |  | 0 |  |  | 0 | AllplanAttributes - Sicherheitsklasse: -
 | H2 Ebene 0 | WI-HW 60 | 1113Wa 0814251393 | yes |  | m² | Zimmer- und Holzbauarbeiten | Wand | Innenwand 1-Schalig | WI-HW 60 |  |  | 0 | 1113HWa0813975950 | NEW |  |  | 0 | AllplanAttributes - Sicherheitsklasse: -
 | H2 Ebene 0 | WI-GKF | 1113Wa 0814251409 | yes |  | m² | Trockenbauarbeiten | Wand | Innenwand 1-Schalig | WI-GKF |  |  | 0 | 1113HWa0812812439 | NEW |  |  | 0 |  |  | 0 | AllplanAttributes - Sicherheitsklasse: -
 | H2 Ebene 0 | WI-HW 60 | 1113Wa 0814251410 | yes |  | m² | Zimmer- und Holzbauarbeiten | Wand | Innenwand 1-Schalig | WI-HW 60 |  |  | 0 | 1113HWa0813975950 | NEW |  |  | 0 | AllplanAttributes - Sicherheitsklasse: -
 | H2 Ebene 0 | WI-GKF | 1113Wa 0814251430 | yes |  | m² | Trockenbauarbeiten | Wand | Innenwand 1-Schalig | WI-GKF |  |  | 0 | 1113HWa0812812439 | NEW |  |  | 0 |  |  | 0 | AllplanAttributes - Sicherheitsklasse: -
 | H2 Ebene 0 | WI-HW 60 | 1113Wa 0814251431 | yes |  | m² | Zimmer- und Holzbauarbeiten | Wand | Innenwand 1-Schalig | WI-HW 60 |  |  | 0 | 1113HWa0813975950 | NEW |  |  | 0 | AllplanAttributes - Sicherheitsklasse: -
 | H2 Ebene 0 | WI-LB | 1113Wa 0814016828 | yes |  | m² | Trockenbauarbeiten | Wand | Innenwand 1-Schalig | WI-LB |  |  | 0 | 1113HWa0814016826 |  |  |  | 0 |  |  | 0 | AllplanAttributes - Ortscode_Geschoßbezeichnung: E00; ash_W_Trockenbau_Qualitäten: 13; Sicherheitsklasse: -
 | H2 Ebene 0 | WI-LB | 1113Wa 0812446716 | yes |  | m² | Trockenbauarbeiten | Wand | Innenwand 1-Schalig | WI-LB |  |  | 0 | 1113HWa0812425474 |  |  |  | 0 |  |  | 47 | AllplanAttributes - Ortscode_Geschoßbezeichnung: E00; W_Deckenanschluss: Gleitender Deckenanschluss Fall 03; ash_W_Trockenbau_Qualitäten: 1c; Sicherheitsklasse: -
 | H2 Ebene 0 | WI-LB | 1113Wa 0812982090 | yes |  | m² | Trockenbauarbeiten | Wand | Innenwand 1-Schalig | WI-LB |  |  | 0 | 1113HWa0812982089 |  |  |  |  |  |  | 0 | AllplanAttributes - ash_W_Trockenbau_Qualitäten: 16
 | H2 Ebene 0 | WI-STB | 1113Wa 0814024952 | yes |  | m² | Zimmer- und Holzbauarbeiten | Wand | Innenwand 1-Schalig | WI-STB |  |  | 0 | 1113HWa0814024951 | NEW |  |  | 0 |  |  | 0 | AllplanAttributes - Sicherheitsklasse: -
 | H2 Ebene 0 | WI-STB | 1113Wa 0814024953 | yes |  | m² | Zimmer- und Holzbauarbeiten | Wand | Innenwand 1-Schalig | WI-STB |  |  | 0 | 1113HWa0814024951 | NEW |  |  | 0 |  |  | 0 | AllplanAttributes - Sicherheitsklasse: -
 | H2 Ebene 0 | WI-LB | 1113Wa 0814024954 | yes |  | m² | Trockenbauarbeiten | Wand | Innenwand 1-Schalig | WI-LB |  |  | 0 | 1113HWa0814024951 | NEW |  |  | 0 |  |  | 0 | AllplanAttributes - ash_W_Trockenbau_Qualitäten: 9; Sicherheitsklasse: -
 | H2 Ebene 0 | WI-STB | 1113Wa 0812444131 | yes |  | m² | Zimmer- und Holzbauarbeiten | Wand | Innenwand 1-Schalig | WI-STB |  |  | 0 | 1113HWa0812428697 | NEW |  |  | 0 |  |  | 0 | AllplanAttributes - Sicherheitsklasse: -
 | H2 Ebene 0 | WI-IW | 1113Wa 0812840160 | yes |  | m² | Trockenbauarbeiten | Wand | Innenwand 1-Schalig | WI-IW |  |  | 0 | 1113HWa0812428697 | NEW |  |  | 0 | AllplanAttributes - ash_W_Trockenbau_Qualitäten: 9; Sicherheitsklasse: -
 | H2 Ebene 0 | WI-HW 60 | 1113Wa 0814026618 | yes |  | m² | Zimmer- und Holzbauarbeiten | Wand | Innenwand 1-Schalig | WI-HW 60 |  |  | 0 | 1113HWa0814026617 | NEW |  |  | 0 |  |  | 0 | AllplanAttributes - Sicherheitsklasse: -
 | H2 Ebene 0 | WI-IW | 1113Wa 0814026692 | yes |  | m² | Trockenbauarbeiten | Wand | Innenwand 1-Schalig | WI-IW |  |  | 0 | 1113HWa0814026617 | NEW |  |  | 0 | AllplanAttributes - ash_W_Trockenbau_Qualitäten: 19; Sicherheitsklasse: -
 | H2 Ebene 0 | WI-LB | 1113Wa 0812443671 | yes |  | m² | Trockenbauarbeiten | Wand | Innenwand 1-Schalig | WI-LB |  |  | 0 | 1113HWa0812428695 | OTHER |  |  | 0 | AllplanAttributes - ash_W_Trockenbau_Qualitäten: 9; Sicherheitsklasse: -
 | H2 Ebene 0 | WI-STB | 1113Wa 0812840229 | yes |  | m² | Zimmer- und Holzbauarbeiten | Wand | Innenwand 1-Schalig | WI-STB |  |  | 0 | 1113HWa0812428695 | NEW |  |  | 0 |  |  | 0 | AllplanAttributes - ash D_Detailverweis: Lösch; ash D_Plannummer: 1682; Sicherheitsklasse: -
 | H2 Ebene 0 | WI-LB | 1113Wa 0814166079 | yes |  | m² | Trockenbauarbeiten | Wand | Innenwand 1-Schalig | WI-LB |  |  | 0 | 1113HWa0814166078 |  |  |  | 0 | AllplanAttributes - ash_W_Trockenbau_Qualitäten: 16; Sicherheitsklasse: -
 | H2 Ebene 0 | WI-HW 60 | 1113Wa 0814166082 | yes |  | m² | Zimmer- und Holzbauarbeiten | Wand | Innenwand 1-Schalig | WI-HW 60 |  |  | 0 | 1113HWa0814166078 |  |  |  | 0 |  |  | 0 | AllplanAttributes - Sicherheitsklasse: -
 | H2 Ebene 0 | WI-LB | 1113Wa 0812443005 | yes |  | m² | Trockenbauarbeiten | Wand | Innenwand 1-Schalig | WI-LB |  |  | 0 | 1113HWa0812441885 | NEW | no |  | 0 | AllplanAttributes - W_Deckenanschluss: Gleitender Deckenanschluss Fall 01; ash_W_Trockenbau_Qualitäten: 16; Sicherheitsklasse: -
 | H2 Ebene 0 | WI-HW 60 | 1113Wa 0813117404 | yes |  | m² | Zimmer- und Holzbauarbeiten | Wand | Innenwand 1-Schalig | WI-HW 60 |  |  | 0 | 1113HWa0812441885 | NEW | no |  | 0 |  |  | 0 | AllplanAttributes - Sicherheitsklasse: -
 | H2 Ebene 0 | WI-LB | 1113Wa 0814179261 | yes |  | m² | Trockenbauarbeiten | Wand | Innenwand 1-Schalig | WI-LB |  |  | 0 | 1113HWa0814179240 | NEW | no |  | 0 | AllplanAttributes - W_Deckenanschluss: Gleitender Deckenanschluss Fall 01; ash_W_Trockenbau_Qualitäten: 16; Sicherheitsklasse: -
 | H2 Ebene 0 | WI-HW 60 | 1113Wa 0814179263 | yes |  | m² | Zimmer- und Holzbauarbeiten | Wand | Innenwand 1-Schalig | WI-HW 60 |  |  | 0 | 1113HWa0814179240 | NEW | no |  | 0 |  |  | 0 | AllplanAttributes - Sicherheitsklasse: -
 | H2 Ebene 0 | WI-LB | 1113Wa 0812810801 | yes |  | m² | Trockenbauarbeiten | Wand | Innenwand 1-Schalig | WI-LB |  |  | 0 | 1113HWa0812810800 |  |  |  | 0 | AllplanAttributes - ash_W_Trockenbau_Qualitäten: 9; Sicherheitsklasse: -
 | H2 Ebene 0 | WI-LB | 1113Wa 0814167984 | yes |  | m² | Trockenbauarbeiten | Wand | Innenwand 1-Schalig | WI-LB |  |  | 0 | 1113HWa0814167983 |  |  |  | 0 | AllplanAttributes - ash_W_Trockenbau_Qualitäten: 9; Sicherheitsklasse: -
 | H2 Ebene 0 | WI-LB | 1113Wa 0814167994 | yes |  | m² | Trockenbauarbeiten | Wand | Innenwand 1-Schalig | WI-LB |  |  | 0 | 1113HWa0814167992 |  |  |  | 0 | AllplanAttributes - ash_W_Trockenbau_Qualitäten: 9; Sicherheitsklasse: -
 | H2 Ebene 0 | WI-LB | 1113Wa 0812840020 | yes |  | m² | Trockenbauarbeiten | Wand | Innenwand 1-Schalig | WI-LB |  |  | 0 | 1113HWa0812840019 |  |  |  | 0 | AllplanAttributes - ash_W_Trockenbau_Qualitäten: 9; Sicherheitsklasse: -
 | H2 Ebene 0 | WI-LB | 1113Wa 0812840038 | yes |  | m² | Trockenbauarbeiten | Wand | Innenwand 1-Schalig | WI-LB |  |  | 0 | 1113HWa0812840037 |  |  |  | 0 | AllplanAttributes - ash_W_Trockenbau_Qualitäten: 9; Sicherheitsklasse: -
 | H2 Ebene 0 | WI-LB | 1113Wa 0814233882 | yes |  | m² | Trockenbauarbeiten | Wand | Innenwand 1-Schalig | WI-LB |  |  | 0 | 1113HWa0812551348 |  |  |  | 0 | AllplanAttributes - ash_W_Trockenbau_Qualitäten: 16; Sicherheitsklasse: -
 | H2 Ebene 0 | WI-HW 60 | 1113Wa 0814233885 | yes |  | m² | Zimmer- und Holzbauarbeiten | Wand | Innenwand 1-Schalig | WI-HW 60 |  |  | 0 | 1113HWa0812551348 |  |  |  | 0 |  |  | 0 | AllplanAttributes - Sicherheitsklasse: -
 | H2 Ebene 0 | WI-HW 60 | 1113Wa 0812551371 | yes |  | m² | Zimmer- und Holzbauarbeiten | Wand | Innenwand 1-Schalig | WI-HW 60 |  |  | 0 | 1113HWa0812551366 |  |  |  | 0 |  |  | 0 | AllplanAttributes - Sicherheitsklasse: -
 | H2 Ebene 0 | WI-LB | 1113Wa 0813421754 | yes |  | m² | Trockenbauarbeiten | Wand | Innenwand 1-Schalig | WI-LB |  |  | 0 | 1113HWa0812551366 |  |  |  | 0 | AllplanAttributes - ash_W_Trockenbau_Qualitäten: 16; Sicherheitsklasse: -
 | H2 Ebene 0 | WI-LB | 1113Wa 0813017170 | yes |  | m² | Trockenbauarbeiten | Wand | Innenwand 1-Schalig | WI-LB |  |  | 0 | 1113HWa0813017160 | NEW |  |  | 0 |  |  | 47 | AllplanAttributes - W_Deckenanschluss: Gleitender Deckenanschluss Fall 01; ash_W_Trockenbau_Qualitäten: 1a; Sicherheitsklasse: -
 | H2 Ebene 0 | WI-LB | 1113Wa 0814027619 | yes |  | m² | Trockenbauarbeiten | Wand | Innenwand 1-Schalig | WI-LB |  |  | 0 | 1113HWa0814027618 |  |  |  | 0 |  |  | 47 | AllplanAttributes - W_Deckenanschluss: Gleitender Deckenanschluss Fall 01; ash_W_Trockenbau_Qualitäten: 1b; Sicherheitsklasse: -
 | H2 Ebene 0 | WI-LB | 1113Wa 0813017169 | yes |  | m² | Trockenbauarbeiten | Wand | Innenwand 1-Schalig | WI-LB |  |  | 0 | 1113HWa0813017159 |  |  |  | 0 |  |  | 47 | AllplanAttributes - Ortscode_Geschoßbezeichnung: E00; W_Deckenanschluss: Gleitender Deckenanschluss Fall 01; ash_W_Trockenbau_Qualitäten: 1b; Sicherheitsklasse: -
 | H2 Ebene 0 | WI-LB | 1113Wa 0812442543 | yes |  | m² | Trockenbauarbeiten | Wand | Innenwand 1-Schalig | WI-LB |  |  | 0 | 1113HWa0812425642 |  |  |  | 0 |  |  | 47 | AllplanAttributes - Ortscode_Geschoßbezeichnung: E00; W_Deckenanschluss: Gleitender Deckenanschluss Fall 01; ash_W_Trockenbau_Qualitäten: 1b; Sicherheitsklasse: -
 | H2 Ebene 0 | WI-VS | 1113Wa 0813046878 | yes |  | m² | Trockenbauarbeiten | Wand | Installationswand | WI-VS |  |  | 0 | 1113HWa0813046877 |  |  |  | 0 | AllplanAttributes - ash_W_Trockenbau_Qualitäten: 16; Sicherheitsklasse: -
 | H2 Ebene 0 | WI-LB | 1113Wa 0814241987 | yes |  | m² | Trockenbauarbeiten | Wand | Innenwand 1-Schalig | WI-LB |  |  | 0 | 1113HWa0812438083 |  |  |  | 0 |  |  | 47 | AllplanAttributes - ash_W_Trockenbau_Qualitäten: 8; Sicherheitsklasse: -
 | H2 Ebene 0 | Installationsraum | 1113Wa 0814241988 | yes |  | m² | Trockenbauarbeiten | Wand | Innenwand 1-Schalig | Installationsraum |  |  | 0 | 1113HWa0812438083 |  |  |  | 0 |  |  | 0 | AllplanAttributes - Sicherheitsklasse: -
 | H2 Ebene 0 | WI-HW 60 | 1113Wa 0814241989 | yes |  | m² | Zimmer- und Holzbauarbeiten | Wand | Innenwand 1-Schalig | WI-HW 60 |  |  | 0 | 1113HWa0812438083 |  |  |  | 0 |  |  | 47 | AllplanAttributes - Sicherheitsklasse: -
 | H2 Ebene 0 | WI-HW 60 | 1113Wa 0813708545 | yes |  | m² | Zimmer- und Holzbauarbeiten | Wand | Innenwand 1-Schalig | WI-HW 60 |  |  | 0 | 1113HWa0813708533 |  |  |  | 0 |  |  | 52 | AllplanAttributes - Sicherheitsklasse: -
 | H2 Ebene 0 | Installationsraum | 1113Wa 0813708543 | yes |  | m² | Trockenbauarbeiten | Wand | Innenwand 1-Schalig | Installationsraum |  |  | 0 | 1113HWa0813708533 |  |  |  | 0 |  |  | 52 | AllplanAttributes - Sicherheitsklasse: -
 | H2 Ebene 0 | WI-LB | 1113Wa 0813708544 | yes |  | m² | Trockenbauarbeiten | Wand | Innenwand 1-Schalig | WI-LB |  |  | 0 | 1113HWa0813708533 |  |  |  | 0 |  |  | 52 | AllplanAttributes - ash_W_Trockenbau_Qualitäten: 6; Sicherheitsklasse: -
 | H2 Ebene 0 | WI-HW 60 | 1113Wa 0813692861 | yes |  | m² | Zimmer- und Holzbauarbeiten | Wand | Innenwand 1-Schalig | WI-HW 60 |  |  | 0 | 1113HWa0813692846 | NEW |  |  | 0 |  |  | 52 | AllplanAttributes - Sicherheitsklasse: -
 | H2 Ebene 0 | WI-LB | 1113Wa 0813692860 | yes |  | m² | Trockenbauarbeiten | Wand | Innenwand 1-Schalig | WI-LB |  |  | 0 | 1113HWa0813692846 | OTHER |  |  | 0 |  |  | 52 | AllplanAttributes - ash_W_Trockenbau_Qualitäten: 6; Sicherheitsklasse: -
 | H2 Ebene 0 | WI-LB | 1113Wa 0812543262 | yes |  | m² | Trockenbauarbeiten | Wand | Innenwand 1-Schalig | WI-LB |  |  | 0 | 1113HWa0812543150 |  |  |  | 0 |  |  | 52 | AllplanAttributes - ash_W_Trockenbau_Qualitäten: 6; Sicherheitsklasse: -
 | H2 Ebene 0 | Installationsraum | 1113Wa 0813129542 | yes |  | m² | Trockenbauarbeiten | Wand | Innenwand 1-Schalig | Installationsraum |  |  | 0 | 1113HWa0812543150 |  |  |  | 0 |  |  | 52 | AllplanAttributes - Sicherheitsklasse: -
 | H2 Ebene 0 | WI-HW 60 | 1113Wa 0813129543 | yes |  | m² | Zimmer- und Holzbauarbeiten | Wand | Innenwand 1-Schalig | WI-HW 60 |  |  | 0 | 1113HWa0812543150 |  |  |  | 0 |  |  | 52 | AllplanAttributes - Sicherheitsklasse: -
 | H2 Ebene 0 | WI-LB | 1113Wa 0813813775 | yes |  | m² | Trockenbauarbeiten | Wand | Innenwand 1-Schalig | WI-LB |  |  | 0 | 1113HWa0813813773 |  |  |  | 0 |  |  | 52 | AllplanAttributes - ash_W_Trockenbau_Qualitäten: 6; Sicherheitsklasse: -
 | H2 Ebene 0 | WI-HW 60 | 1113Wa 0813813774 | yes |  | m² | Zimmer- und Holzbauarbeiten | Wand | Innenwand 1-Schalig | WI-HW 60 |  |  | 0 | 1113HWa0813813773 |  |  |  | 0 |  |  | 52 | AllplanAttributes - Sicherheitsklasse: -
 | H2 Ebene 0 | WI-LB | 1113Wa 0812754801 |  |  | m² | Trockenbauarbeiten | Wand | Innenwand 1-Schalig | WI-LB |  |  | 0 | 1113HWa0812754799 |  |  |  | 0 |  |  | 47 | AllplanAttributes - ash_W_Trockenbau_Qualitäten: 7; Sicherheitsklasse: -
 | H2 Ebene 0 | WI-HW 60 | 1113Wa 0813145141 |  |  | m² | Zimmer- und Holzbauarbeiten | Wand | Innenwand 1-Schalig | WI-HW 60 |  |  | 0 | 1113HWa0812754799 |  |  |  | 0 |  |  | 47 | AllplanAttributes - Sicherheitsklasse: -
 | H2 Ebene 0 | WI-LB | 1113Wa 0812438677 |  |  | m² | Trockenbauarbeiten | Wand | Innenwand 1-Schalig | WI-LB |  |  | 0 | 1113HWa0812438496 |  |  |  | 0 |  |  | 52 | AllplanAttributes - ash_W_Trockenbau_Qualitäten: 7; Sicherheitsklasse: -
 | H2 Ebene 0 | WI-HW 60 | 1113Wa 0813145110 |  |  | m² | Zimmer- und Holzbauarbeiten | Wand | Innenwand 1-Schalig | WI-HW 60 |  |  | 0 | 1113HWa0812438496 |  |  |  | 0 |  |  | 52 | AllplanAttributes - Sicherheitsklasse: -
 | H2 Ebene 0 | WI-VS | 1113Wa 0812437932 | yes |  | m² | Trockenbauarbeiten | Wand | Innenwand 1-Schalig | WI-VS |  |  | 0 | 1113HWa0812434549 | NEW |  |  | 0 | AllplanAttributes - ash_W_Trockenbau_Qualitäten: 16; Sicherheitsklasse: -
 | H2 Ebene 0 | WI-HW 60 | 1113Wa 0813940327 | yes |  | m² | Zimmer- und Holzbauarbeiten | Wand | Innenwand 1-Schalig | WI-HW 60 |  |  | 0 | 1113HWa0812434549 | NEW |  |  | 0 |  |  | 52 | AllplanAttributes - Sicherheitsklasse: -
 | H2 Ebene 0 | WI-LB | 1113Wa 0812437264 | yes |  | m² | Trockenbauarbeiten | Wand | Innenwand 1-Schalig | WI-LB |  |  | 0 | 1113HWa0812434427 |  |  |  | 0 |  |  | 52 | AllplanAttributes - ash_W_Trockenbau_Qualitäten: 6; Sicherheitsklasse: -
 | H2 Ebene 0 | Installationsraum | 1113Wa 0813139914 | yes |  | m² | Trockenbauarbeiten | Wand | Innenwand 1-Schalig | Installationsraum |  |  | 0 | 1113HWa0812434427 |  |  |  | 0 |  |  | 52 | AllplanAttributes - Sicherheitsklasse: -
 | H2 Ebene 0 | WI-HW 60 | 1113Wa 0813139915 | yes |  | m² | Zimmer- und Holzbauarbeiten | Wand | Innenwand 1-Schalig | WI-HW 60 |  |  | 0 | 1113HWa0812434427 |  |  |  | 0 |  |  | 52 | AllplanAttributes - Sicherheitsklasse: -
 | H2 Ebene 0 | WI-LB | 1113Wa 0812520562 | yes |  | m² | Trockenbauarbeiten | Wand | Innenwand 1-Schalig | WI-LB |  |  | 0 | 1113HWa0812520561 |  |  |  | 0 |  |  | 52 | AllplanAttributes - ash_W_Trockenbau_Qualitäten: 6; Sicherheitsklasse: -
 | H2 Ebene 0 | WI-HW 60 | 1113Wa 0813138450 | yes |  | m² | Zimmer- und Holzbauarbeiten | Wand | Innenwand 1-Schalig | WI-HW 60 |  |  | 0 | 1113HWa0812520561 |  |  |  | 0 |  |  | 52 | AllplanAttributes - Sicherheitsklasse: -
 | H2 Ebene 0 | WI-STB | 1113Wa 0813453141 | yes |  | m² | Zimmer- und Holzbauarbeiten | Wand | Innenwand 1-Schalig | WI-STB |  |  | 0 | 1113HWa0813452913 | NEW |  |  | 0 |  |  | 0 | AllplanAttributes - Sicherheitsklasse: -
 | H2 Ebene 0 | WI-LB | 1113Wa 0813453140 | yes |  | m² | Trockenbauarbeiten | Wand | Innenwand 1-Schalig | WI-LB |  |  | 0 | 1113HWa0813452913 | OTHER |  |  | 0 | AllplanAttributes - ash_W_Trockenbau_Qualitäten: 16; Sicherheitsklasse: -
 | H2 Ebene 0 | WI-HW 60 | 1113Wa 0812553865 | yes |  | m² | Zimmer- und Holzbauarbeiten | Wand | Innenwand 1-Schalig | WI-HW 60 |  |  | 0 | 1113HWa0812553533 |  |  |  | 0 |  |  | 42 | AllplanAttributes - Sicherheitsklasse: -
 | H2 Ebene 0 | WI-LB | 1113Wa 0813418548 | yes |  | m² | Trockenbauarbeiten | Wand | Innenwand 1-Schalig | WI-LB |  |  | 0 | 1113HWa0812553533 |  |  |  | 0 | AllplanAttributes - ash_W_Trockenbau_Qualitäten: 16; Sicherheitsklasse: -
 | H2 Ebene 0 | WI-HW 60 | 1113Wa 0813936885 | yes |  | m² | Zimmer- und Holzbauarbeiten | Wand | Innenwand 1-Schalig | WI-HW 60 |  |  | 0 | 1113HWa0813936884 |  |  |  | 0 |  |  | 42 | AllplanAttributes - Sicherheitsklasse: -
 | H2 Ebene 0 | WI-LB | 1113Wa 0813936886 | yes |  | m² | Trockenbauarbeiten | Wand | Innenwand 1-Schalig | WI-LB |  |  | 0 | 1113HWa0813936884 |  |  |  | 0 | AllplanAttributes - ash_W_Trockenbau_Qualitäten: 20; Sicherheitsklasse: -
 | H2 Ebene 0 | WI-LB | 1113Wa 0812447118 | yes |  | m² | Trockenbauarbeiten | Wand | Innenwand 1-Schalig | WI-LB |  |  | 0 | 1113HWa0812430571 |  |  |  | 0 |  |  | 52 | AllplanAttributes - ash_W_Trockenbau_Qualitäten: 6; Sicherheitsklasse: -
 | H2 Ebene 0 | Installationsraum | 1113Wa 0813125542 | yes |  | m² | Trockenbauarbeiten | Wand | Innenwand 1-Schalig | Installationsraum |  |  | 0 | 1113HWa0812430571 |  |  |  | 0 |  |  | 52 | AllplanAttributes - Sicherheitsklasse: -
 | H2 Ebene 0 | WI-HW 60 | 1113Wa 0813125543 | yes |  | m² | Zimmer- und Holzbauarbeiten | Wand | Innenwand 1-Schalig | WI-HW 60 |  |  | 0 | 1113HWa0812430571 |  |  |  | 0 |  |  | 52 | AllplanAttributes - Sicherheitsklasse: -
 | H2 Ebene 0 | WI-LB | 1113Wa 0812437318 | yes |  | m² | Trockenbauarbeiten | Wand | Innenwand 1-Schalig | WI-LB |  |  | 0 | 1113HWa0812434265 |  |  |  | 0 |  |  | 52 | AllplanAttributes - ash_W_Trockenbau_Qualitäten: 6; Sicherheitsklasse: -
 | H2 Ebene 0 | WI-HW 60 | 1113Wa 0813138607 | yes |  | m² | Zimmer- und Holzbauarbeiten | Wand | Innenwand 1-Schalig | WI-HW 60 |  |  | 0 | 1113HWa0812434265 |  |  |  | 0 |  |  | 52 | AllplanAttributes - Sicherheitsklasse: -
 | H2 Ebene 0 | WI-LB | 1113Wa 0814190817 | yes |  | m² | Trockenbauarbeiten | Wand | Innenwand 1-Schalig | WI-LB |  |  | 0 | 1113HWa0814190676 | NEW | no |  | 0 |  |  | 47 | AllplanAttributes - W_Deckenanschluss: Gleitender Deckenanschluss Fall 01; ash_W_Trockenbau_Qualitäten: 1d
 | H2 Ebene 0 | WI-LB | 1113Wa 0812705252 | yes |  | m² | Trockenbauarbeiten | Wand | Innenwand 1-Schalig | WI-LB |  |  | 0 | 1113HWa0812705251 |  |  |  | 0 |  |  | 47 | AllplanAttributes - W_Deckenanschluss: Gleitender Deckenanschluss Fall 01; ash_W_Trockenbau_Qualitäten: 1b; Sicherheitsklasse: -
 | H2 Ebene 0 | WI-LB | 1113Wa 0814252215 | yes |  | m² | Trockenbauarbeiten | Wand | Innenwand 1-Schalig | WI-LB |  |  | 0 | 1113HWa0812705251 |  |  |  | 0 |  |  | 0 | AllplanAttributes - W_Deckenanschluss: Gleitender Deckenanschluss Fall 01; ash_W_Trockenbau_Qualitäten: 1b; Sicherheitsklasse: -
 | H2 Ebene 0 | WI-LB | 1113Wa 0812705214 | yes |  | m² | Trockenbauarbeiten | Wand | Innenwand 1-Schalig | WI-LB |  |  | 0 | 1113HWa0812705213 |  |  |  | 0 |  |  | 0 | AllplanAttributes - W_Deckenanschluss: Gleitender Deckenanschluss Fall 01; ash_W_Trockenbau_Qualitäten: 1b; Sicherheitsklasse: -
 | H2 Ebene 0 | WI-LB | 1113Wa 0814252250 | yes |  | m² | Trockenbauarbeiten | Wand | Innenwand 1-Schalig | WI-LB |  |  | 0 | 1113HWa0812705213 |  |  |  | 0 |  |  | 47 | AllplanAttributes - W_Deckenanschluss: Gleitender Deckenanschluss Fall 01; ash_W_Trockenbau_Qualitäten: 1b; Sicherheitsklasse: -
 | H2 Ebene 0 | WI-HW 60 | 1113Wa 0812447107 | yes |  | m² | Zimmer- und Holzbauarbeiten | Wand | Innenwand 1-Schalig | WI-HW 60 |  |  | 0 | 1113HWa0812434283 |  |  |  | 0 |  |  | 52 | AllplanAttributes - Sicherheitsklasse: -
 | H2 Ebene 0 | WI-LB | 1113Wa 0813669643 | yes |  | m² | Trockenbauarbeiten | Wand | Innenwand 1-Schalig | WI-LB |  |  | 0 | 1113HWa0812434283 |  |  |  | 0 |  |  | 52 | AllplanAttributes - ash_W_Trockenbau_Qualitäten: 6; Sicherheitsklasse: -
 | H2 Ebene 0 | WI-IW | 1113Wa 0813047151 | yes |  | m² | Trockenbauarbeiten | Wand | Installationswand | WI-IW |  |  | 0 | 1113HWa0813047150 |  |  |  | 0 | AllplanAttributes - ash_W_Trockenbau_Qualitäten: 6; Sicherheitsklasse: -
 | H2 Ebene 0 | WI-LB | 1113Wa 0814167624 | yes |  | m² | Trockenbauarbeiten | Wand | Innenwand 1-Schalig | WI-LB |  |  | 0 | 1113HWa0814167622 |  |  |  | 0 | AllplanAttributes - ash_W_Trockenbau_Qualitäten: 9; Sicherheitsklasse: -
 | H2 Ebene 0 | WI-LB | 1113Wa 0812474333 | yes |  | m² | Trockenbauarbeiten | Wand | Innenwand 1-Schalig | WI-LB |  |  | 0 | 1113HWa0812474331 |  |  |  | 0 |  |  | 52 | AllplanAttributes - ash_W_Trockenbau_Qualitäten: 6; Sicherheitsklasse: -
 | H2 Ebene 0 | WI-HW 60 | 1113Wa 0813137890 | yes |  | m² | Zimmer- und Holzbauarbeiten | Wand | Innenwand 1-Schalig | WI-HW 60 |  |  | 0 | 1113HWa0812474331 |  |  |  | 0 |  |  | 52 | AllplanAttributes - Sicherheitsklasse: -
 | H2 Ebene 0 | WI-LB | 1113Wa 0814188404 | yes | Codetext | m² | Trockenbauarbeiten | Wand | Innenwand 1-Schalig | WI-LB | 0 | A | 3.75 | 1113HWa0814188403 | NEW | no | no | 0 | 0 | no | 47 | no | Codetext | AllplanAttributes - W_Deckenanschluss: Gleitender Deckenanschluss Fall 01; ash_W_Trockenbau_Qualitäten: 4; Positionsnummer_Text: U100
 | H2 Ebene 0 | WI-STB | 1113Wa 0812447104 | yes |  | m² | Zimmer- und Holzbauarbeiten | Wand | Außenwand 1-Schalig | WI-STB |  |  | 0 | 1113HWa0812430564 | NEW | no |  | 0 | AllplanAttributes - Ortscode_Geschoßbezeichnung: E00; Sicherheitsklasse: -
 | H2 Ebene 0 | WI-HW 60 | 1113Wa 0812446819 |  |  | m² | Zimmer- und Holzbauarbeiten | Wand | Innenwand 1-Schalig | WI-HW 60 |  |  | 0 | 1113HWa0812435298 |  |  |  | 0 |  |  | 47 | AllplanAttributes - Sicherheitsklasse: -
 | H2 Ebene 0 | WI-LB | 1113Wa 0812959984 | yes |  | m² | Trockenbauarbeiten | Wand | Innenwand 1-Schalig | WI-LB |  |  | 0 | 1113HWa0812959982 |  |  |  | 0 |  |  | 52 | AllplanAttributes - ash_W_Trockenbau_Qualitäten: 6; Sicherheitsklasse: -
 | H2 Ebene 0 | WI-HW 60 | 1113Wa 0813420916 | yes |  | m² | Zimmer- und Holzbauarbeiten | Wand | Innenwand 1-Schalig | WI-HW 60 |  |  | 0 | 1113HWa0812959982 |  |  |  | 0 |  |  | 52 | AllplanAttributes - Sicherheitsklasse: -
 | H2 Ebene 0 | WI-HW 60 | 1113Wa 0814252830 |  |  | m² | Zimmer- und Holzbauarbeiten | Wand | Innenwand 1-Schalig | WI-HW 60 |  |  | 0 | 1113HWa0812446815 |  |  |  | 0 | AllplanAttributes - Sicherheitsklasse: -
 | H2 Ebene 0 | WI-HW 60 | 1113Wa 0812446933 | yes |  | m² | Zimmer- und Holzbauarbeiten | Wand | Innenwand 1-Schalig | WI-HW 60 |  |  | 0 | 1113HWa0812446815 |  |  |  | 0 |  |  | 47 | AllplanAttributes - Sicherheitsklasse: -
 | H2 Ebene 0 | WI-LB | 1113Wa 0812446823 | yes |  | m² | Trockenbauarbeiten | Wand | Innenwand 1-Schalig | WI-LB |  |  | 0 | 1113HWa0812430886 |  |  |  | 0 |  |  | 47 | AllplanAttributes - ash_W_Trockenbau_Qualitäten: 8; Sicherheitsklasse: -
 | H2 Ebene 0 | Installationsraum | 1113Wa 0813128732 | yes |  | m² | Trockenbauarbeiten | Wand | Innenwand 1-Schalig | Installationsraum |  |  | 0 | 1113HWa0812430886 |  |  |  | 0 |  |  | 47 | AllplanAttributes - Sicherheitsklasse: -
 | H2 Ebene 0 | WI-HW 60 | 1113Wa 0813129129 | yes |  | m² | Zimmer- und Holzbauarbeiten | Wand | Innenwand 1-Schalig | WI-HW 60 |  |  | 0 | 1113HWa0812430886 |  |  |  | 0 |  |  | 47 | AllplanAttributes - Sicherheitsklasse: -
 | H2 Ebene 0 | WI-HW 60 | 1113Wa 0813244298 | yes |  | m² | Zimmer- und Holzbauarbeiten | Wand | Innenwand 1-Schalig | WI-HW 60 |  |  | 0 | 1113HWa0813244153 |  |  |  | 0 |  |  | 47 | AllplanAttributes - Sicherheitsklasse: -
 | H2 Ebene 0 | WI-STB | 1113Wa 0812542171 | yes |  | m² | Zimmer- und Holzbauarbeiten | Wand | Außenwand 1-Schalig | WI-STB |  |  | 0 | 1113HWa0812542150 | NEW |  |  | 0 |  |  | 0 | AllplanAttributes - Ortscode_Geschoßbezeichnung: E00; Sicherheitsklasse: -
 | H2 Ebene 0 | WI-LB | 1113Wa 0812542159 |  |  | m² | Trockenbauarbeiten | Wand | Außenwand 1-Schalig | WI-LB |  |  | 0 | 1113HWa0812542154 | OTHER |  |  | 0 | AllplanAttributes - ash_W_Trockenbau_Qualitäten: 9; Sicherheitsklasse: -
 | H2 Ebene 0 | WI-STB | 1113Wa 0812842222 | yes |  | m² | Betonarbeiten | Wand | Außenwand 1-Schalig | WI-STB |  |  | 0 | 1113HWa0812542154 | NEW |  |  | 0 |  |  | 52 | AllplanAttributes - Sicherheitsklasse: -
 | H2 Ebene 0 | WI-HW 60 | 1113Wa 0814209304 | yes |  | m² | Zimmer- und Holzbauarbeiten | Wand | Innenwand 1-Schalig | WI-HW 60 |  |  | 0 | 1113HWa0814209303 | NEW |  |  | 0 |  |  | 47 | AllplanAttributes - Sicherheitsklasse: -
 | H2 Ebene 0 | WI-HW 60 | 1113Wa 0812551376 | yes |  | m² | Zimmer- und Holzbauarbeiten | Wand | Innenwand 1-Schalig | WI-HW 60 |  |  | 0 | 1113HWa0812551333 | NEW |  |  | 0 |  |  | 0 | AllplanAttributes - Sicherheitsklasse: -
 | H2 Ebene 0 | WI-LB | 1113Wa 0813119660 | yes |  | m² | Trockenbauarbeiten | Wand | Innenwand 1-Schalig | WI-LB |  |  | 0 | 1113HWa0812551333 | NEW |  |  | 0 | AllplanAttributes - ash_W_Trockenbau_Qualitäten: 16; Sicherheitsklasse: -
 | H2 Ebene 0 | WI-LB | 1113Wa 0812982564 | yes |  | m² | Trockenbauarbeiten | Wand | Innenwand 1-Schalig | WI-LB |  |  | 0 | 1113HWa0812982563 | NEW | no |  |  |  |  | 0 | AllplanAttributes - ash_W_Trockenbau_Qualitäten: 6
 | H2 Ebene 0 | WI-LB | 1113Wa 0814206506 | yes |  | m² | Trockenbauarbeiten | Wand | Innenwand 1-Schalig | WI-LB |  |  | 0 | 1113HWa0814206505 | NEW |  |  | 0 |  |  | 0 | AllplanAttributes - ash D_Detailverweis: D7; ash D_Plannummer: 1684; ash_W_Trockenbau_Qualitäten: 6; Sicherheitsklasse: -
WV 1.1 | H2 Ebene 0 |  | 1113Sma0814160610 |  | VUK5 - Handlauf | St | Trockenbauarbeiten | SmartPart | WV 1.1 |  |  |  | 0.2 |  |  |  |  | - | AllplanAttributes - Text1: WA; V6: 0 m; V7: 0 m; V8: 0 m; V9: 0; Länge: 1.5 m; Dicke: 0.025 m; Höhe: 0.2 m; Programmversion: 3.1; Text3: 0; Plugin_Bezeichnung: MainObject; Plugin_Objektname: SmartPartCompressed; Version: 1.1; Abstand_Öffn_Unten: 0.9 m; ash T_Feuchtebeständigkeit: nein; Feuerwiderstandsklasse~: nein
 | H2 Ebene 0 | WI-HW 60 | 1113Wa 0814187216 | yes |  | m² | Zimmer- und Holzbauarbeiten | Wand | Innenwand 1-Schalig | WI-HW 60 |  |  | 0 | 1113HWa0814187215 | NEW | no |  | 0 |  |  | 47 | AllplanAttributes - Sicherheitsklasse: -
 | H2 Ebene 0 | WI-LB | 1113Wa 0814187250 | yes |  | m² | Trockenbauarbeiten | Wand | Innenwand 1-Schalig | WI-LB |  |  | 0 | 1113HWa0814187215 | NEW | no |  | 0 |  |  | 47 | AllplanAttributes - ash_W_Trockenbau_Qualitäten: 6; Sicherheitsklasse: -
 | H2 Ebene 0 | WI-IW | 1113Wa 0814139199 | yes |  | m² | Trockenbauarbeiten | Wand | Installationswand | WI-IW |  |  | 0 | 1113HWa0814139198 | NEW |  |  | 0 |  |  | 0 | AllplanAttributes - W_Deckenanschluss: Gleitender Deckenanschluss Fall 03; ash_W_Trockenbau_Qualitäten: 2; Sicherheitsklasse: -
 | H2 Ebene 0 | Installationsraum | 1113Wa 0814139200 | yes |  | m² | Trockenbauarbeiten | Wand | Installationswand | Installationsraum |  |  | 0 | 1113HWa0814139198 | NEW |  |  | 0 |  |  | 0 | AllplanAttributes - Sicherheitsklasse: -
 | H2 Ebene 0 | WI-LB | 1113Wa 0812438246 | yes |  | m² | Trockenbauarbeiten | Wand | Innenwand 1-Schalig | WI-LB |  |  | 0 | 1113HWa0812425522 | NEW |  |  | 0 |  |  | 0 | AllplanAttributes - Ortscode_Geschoßbezeichnung: E00; W_Deckenanschluss: Gleitender Deckenanschluss Fall 03; ash_W_Trockenbau_Qualitäten: 10a; Sicherheitsklasse: -
 | H2 Ebene 0 | WI-HW 60 | 1113Wa 0814138723 | yes |  | m² | Zimmer- und Holzbauarbeiten | Wand | Innenwand 1-Schalig | WI-HW 60 |  |  | 0 | 1113HWa0814138517 | NEW |  |  | 0 |  |  | 47 | AllplanAttributes - Sicherheitsklasse: -
 | H2 Ebene 0 | WI-LB | 1113Wa 0812437392 | yes |  | m² | Trockenbauarbeiten | Wand | Außenwand 1-Schalig | WI-LB |  |  | 0 | 1113HWa0812425634 | NEW |  |  | 0 |  |  | 0 | AllplanAttributes - Ortscode_Geschoßbezeichnung: E00; W_Deckenanschluss: Gleitender Deckenanschluss Fall 01; ash_W_Trockenbau_Qualitäten: 1b; Sicherheitsklasse: -
 | H2 Ebene 0 | WI-HW 60 | 1113Wa 0814022335 | yes |  | m² | Zimmer- und Holzbauarbeiten | Wand | Innenwand 1-Schalig | WI-HW 60 |  |  | 0 | 1113HWa0814022334 | NEW | no |  | 0 |  |  | 0 | AllplanAttributes - Sicherheitsklasse: -
 | H2 Ebene 0 | WI-IW | 1113Wa 0812437662 | yes |  | m² | Trockenbauarbeiten | Wand | Installationswand | WI-IW |  |  | 0 | 1113HWa0812425829 | NEW | no |  | 0 |  |  | 0 | AllplanAttributes - W_Deckenanschluss: Gleitender Deckenanschluss Fall 01; ash_W_Trockenbau_Qualitäten: 11; Sicherheitsklasse: -
 | H2 Ebene 0 | Installationsraum | 1113Wa 0812437660 | yes |  | m² | Trockenbauarbeiten | Wand | Installationswand | Installationsraum |  |  | 0 | 1113HWa0812425829 | NEW | no |  | 0 |  |  | 0 | AllplanAttributes - Sicherheitsklasse: -
 | H2 Ebene 0 | WI-IW | 1113Wa 0812437238 | yes |  | m² | Trockenbauarbeiten | Wand | Installationswand | WI-IW |  |  | 0 | 1113HWa0812425829 | NEW | no |  | 0 |  |  | 0 | AllplanAttributes - W_Deckenanschluss: Gleitender Deckenanschluss Fall 01; ash_W_Trockenbau_Qualitäten: 11; Sicherheitsklasse: -
 | H2 Ebene 0 | WI-HW 60 | 1113Wa 0814142685 | yes |  | m² | Zimmer- und Holzbauarbeiten | Wand | Innenwand 1-Schalig | WI-HW 60 |  |  | 0 | 1113HWa0814142502 | NEW | no |  | 0 |  |  | 47 | AllplanAttributes - Sicherheitsklasse: -
 | H2 Ebene 0 | WI-RIR | 1113Wa 0814006162 | yes |  | m² | Tischlerarbeiten | Wand | Innenwand 1-Schalig | WI-RIR |  |  | 0 | 1113HWa0814006161 | NEW | no |  | 0 |  |  | 47 | AllplanAttributes - ash_W_Trockenbau_Qualitäten: 1b
 | H2 Ebene 0 | WI-RIR | 1113Wa 0814190720 | yes |  | m² | Tischlerarbeiten | Wand | Innenwand 1-Schalig | WI-RIR |  |  | 0 | 1113HWa0814190672 | NEW |  |  | 0 |  |  | 47 | AllplanAttributes - ash D_Detailverweis: D6; ash D_Plannummer: 1684; W_Deckenanschluss: Gleitender Deckenanschluss Fall 01; ash_W_Trockenbau_Qualitäten: 1b
 | H2 Ebene 0 | WI-RIR | 1113Wa 0814190697 | yes |  | m² | Tischlerarbeiten | Wand | Innenwand 1-Schalig | WI-RIR |  |  | 0 | 1113HWa0814190673 | NEW | no |  | 0 |  |  | 47 | AllplanAttributes - ash_W_Trockenbau_Qualitäten: 1b
 | H2 Ebene 0 | WI-LB | 1113Wa 0814281616 | yes |  | m² | Trockenbauarbeiten | Wand | Innenwand 1-Schalig | WI-LB |  |  | 0 | 1113HWa0812438171 | NEW |  |  | 0 |  |  | 0 | AllplanAttributes - W_Deckenanschluss: Gleitender Deckenanschluss Fall 01; ash_W_Trockenbau_Qualitäten: 12b; Sicherheitsklasse: -
 | H2 Ebene 0 | WI-LB | 1113Wa 0812446151 | yes |  | m² | Trockenbauarbeiten | Wand | Innenwand 1-Schalig | WI-LB |  |  | 0 | 1113HWa0812434274 | NEW |  |  | 0 |  |  | 0 | AllplanAttributes - W_Deckenanschluss: Gleitender Deckenanschluss Fall 01; ash_W_Trockenbau_Qualitäten: 12b; Sicherheitsklasse: -
 | H2 Ebene 0 | WI-LB | 1113Wa 0812438684 | yes |  | m² | Trockenbauarbeiten | Wand | Innenwand 1-Schalig | WI-LB |  |  | 0 | 1113HWa0812438171 | NEW |  |  | 0 |  |  | 0 | AllplanAttributes - W_Deckenanschluss: Gleitender Deckenanschluss Fall 01; ash_W_Trockenbau_Qualitäten: 12b; Sicherheitsklasse: -
 | H2 Ebene 0 | WI-LB | 1113Wa 0812889012 |  |  | m² | Trockenbauarbeiten | Wand | Innenwand 1-Schalig | WI-LB |  |  | 0 | 1113HWa0812889011 | OTHER |  |  | 0 | AllplanAttributes - ash_W_Trockenbau_Qualitäten: 6; Sicherheitsklasse: -
 | H2 Ebene 0 | WI-STB | 1113Wa 0812889013 | yes |  | m² | Zimmer- und Holzbauarbeiten | Wand | Innenwand 1-Schalig | WI-STB |  |  | 0 | 1113HWa0812889011 | NEW |  |  | 0 |  |  | 0 | AllplanAttributes - Sicherheitsklasse: -
 | H2 Ebene 0 | WI-LB | 1113Wa 0814282863 | yes |  | m² | Trockenbauarbeiten | Wand | Innenwand 1-Schalig | WI-LB |  |  | 0 | 1113HWa0812889011 | NEW |  |  | 0 | AllplanAttributes - ash_W_Trockenbau_Qualitäten: 6; Sicherheitsklasse: -
 | H2 Ebene 0 | WI-STB | 1113Wa 0814282866 | yes |  | m² | Zimmer- und Holzbauarbeiten | Wand | Innenwand 1-Schalig | WI-STB |  |  | 0 | 1113HWa0812889011 | NEW |  |  | 0 |  |  | 0 | AllplanAttributes - Sicherheitsklasse: -
 | H2 Ebene 0 | WI-LB | 1113Wa 0814282937 | yes |  | m² | Trockenbauarbeiten | Wand | Innenwand 1-Schalig | WI-LB |  |  | 0 | 1113HWa0812430573 | NEW |  |  | 0 | AllplanAttributes - ash_W_Trockenbau_Qualitäten: 9; Sicherheitsklasse: -
 | H2 Ebene 0 | BS Beplankung | 1113Wa 0814207271 | yes |  | m² | Tischlerarbeiten | Wand | Innenwand 1-Schalig | BS Beplankung |  |  | 0 | 1113HWa0814206303 | NEW | no |  | 0 |  |  | 0 | AllplanAttributes - ash_W_Trockenbau_Qualitäten: 1
 | H2 Ebene 0 | BS Beplankung | 1113Wa 0814207074 | yes |  | m² | Tischlerarbeiten | Wand | Innenwand 1-Schalig | BS Beplankung |  |  | 0 | 1113HWa0814206303 | NEW | no |  | 0 |  |  | 0 | AllplanAttributes - W_Deckenanschluss: Gleitender Deckenanschluss Fall 01; ash_W_Trockenbau_Qualitäten: 1
 | H2 Ebene 0 | WI-STB | 1113Wa 0812439603 |  |  | m² | Zimmer- und Holzbauarbeiten | Wand | Außenwand 1-Schalig | WI-STB |  |  | 0 | 1113HWa0812428690 |  |  |  | 0 |  |  | 0 | AllplanAttributes - Ortscode_Geschoßbezeichnung: E00; Sicherheitsklasse: -
 | H2 Ebene 0 | WI-STB | 1113Wa 0812840575 |  |  | m² | Zimmer- und Holzbauarbeiten | Wand | Innenwand 1-Schalig | WI-STB |  |  | 0 | 1113HWa0812840573 |  |  |  | 0 |  |  | 0 | AllplanAttributes - Ortscode_Geschoßbezeichnung: E00; Sicherheitsklasse: -
 | H2 Ebene 0 | WI-STB | 1113Wa 0812443669 |  |  | m² | Zimmer- und Holzbauarbeiten | Wand | Innenwand 1-Schalig | WI-STB |  |  | 0 | 1113HWa0812430718 |  |  |  | 0 |  |  | 0 | AllplanAttributes - Ortscode_Geschoßbezeichnung: E00; Sicherheitsklasse: -
 | H2 Ebene 0 | WI-STB | 1113Wa 0812437244 |  |  | m² | Zimmer- und Holzbauarbeiten | Wand | Außenwand 1-Schalig | WI-STB |  |  | 0 | 1113HWa0812428689 |  |  |  | 0 |  |  | 0 | AllplanAttributes - Ortscode_Geschoßbezeichnung: E00; Sicherheitsklasse: -
 | H2 Ebene 0 | WI-STB | 1113Wa 0812437765 |  |  | m² | Zimmer- und Holzbauarbeiten | Wand | Außenwand 1-Schalig | WI-STB |  |  | 0 | 1113HWa0812428686 |  |  |  | 0 |  |  | 0 | AllplanAttributes - Sicherheitsklasse: -
 | H2 Ebene 0 | WI-STB | 1113Wa 0812438050 |  |  | m² | Zimmer- und Holzbauarbeiten | Wand | Innenwand 1-Schalig | WI-STB |  |  | 0 | 1113HWa0812435122 |  |  |  | 0 | AllplanAttributes - Ortscode_Geschoßbezeichnung: E00; Sicherheitsklasse: -
 | H2 Ebene 0 | WI-STB | 1113Wa 0812447417 |  |  | m² | Zimmer- und Holzbauarbeiten | Wand | Innenwand 1-Schalig | WI-STB |  |  | 0 | 1113HWa0812437907 |  |  |  | 0 | AllplanAttributes - Ortscode_Geschoßbezeichnung: E00; Sicherheitsklasse: -
 | H2 Ebene 0 | WI-STB | 1113Wa 0813889089 |  |  | m² | Zimmer- und Holzbauarbeiten | Wand | Außenwand 1-Schalig | WI-STB |  |  | 0 | 1113HWa0813889088 |  |  |  | 0 | AllplanAttributes - Sicherheitsklasse: -
 | H2 Ebene 0 | WI-STB | 1113Wa 0813910542 | yes |  | m² | Zimmer- und Holzbauarbeiten | Wand | Außenwand 1-Schalig | WI-STB |  |  | 0 | 1113HWa0813910541 |  |  |  | 0 |  |  | 0 | AllplanAttributes - Text1: Feinputz an Wandseite zum Speisewagenraum; Sicherheitsklasse: -
 | H2 Ebene 0 | WI-STB | 1113Wa 0814024283 | yes |  | m² | Zimmer- und Holzbauarbeiten | Wand | Innenwand 1-Schalig | WI-STB |  |  | 0 | 1113HWa0814024222 | NEW | no |  | 0 |  |  | 0 | AllplanAttributes - Sicherheitsklasse: -
 | H2 Ebene 0 | WI-LB | 1113Wa 0814024282 |  |  | m² | Trockenbauarbeiten | Wand | Innenwand 1-Schalig | WI-LB |  |  | 0 | 1113HWa0814024222 | OTHER |  |  | 0 | AllplanAttributes - ash_W_Trockenbau_Qualitäten: 9; Sicherheitsklasse: -
 | H2 Ebene 0 | WI-STB | 1113Wa 0814023119 | yes |  | m² | Zimmer- und Holzbauarbeiten | Wand | Innenwand 1-Schalig | WI-STB |  |  | 0 | 1113HWa0814023118 | NEW | no |  | 0 |  |  | 0 | AllplanAttributes - Sicherheitsklasse: -
 | H2 Ebene 0 | WI-LB | 1113Wa 0812846194 |  |  | m² | Trockenbauarbeiten | Wand | Außenwand 1-Schalig | WI-LB |  |  | 0 | 1113HWa0812846192 |  |  |  | 0 | AllplanAttributes - ash_W_Trockenbau_Qualitäten: 9; Sicherheitsklasse: -
 | H2 Ebene 0 | WI-STB | 1113Wa 0812846226 |  |  | m² | Zimmer- und Holzbauarbeiten | Wand | Außenwand 1-Schalig | WI-STB |  |  | 0 | 1113HWa0812846192 |  |  |  | 0 |  |  | 0 | AllplanAttributes - Sicherheitsklasse: -
 | H2 Ebene 0 | BS Beplankung | 1113Wa 0812812558 |  |  | m² | Trockenbauarbeiten | Wand | """""""""""""""BS-Beplankung; 2-fach Gipsfaserplatten""""""""""""""" | BS Beplankung |  |  | 0 | 1113HWa0812812557 |  |  |  |  |  |  | 0 | AllplanAttributes - Sicherheitsklasse: -
 | H2 Ebene 0 | BS Beplankung | 1113Wa 0812812546 |  |  | m² | Trockenbauarbeiten | Wand | """""""""""""""BS-Beplankung; 2-fach Gipsfaserplatten""""""""""""""" | BS Beplankung |  |  | 0 | 1113HWa0812812545 |  |  |  |  |  |  | 0 | AllplanAttributes - Sicherheitsklasse: -
 | H2 Ebene 0 | BS Beplankung | 1113Wa 0812812539 |  |  | m² | Trockenbauarbeiten | Wand | """""""""""""""BS-Beplankung; 2-fach Gipsfaserplatten""""""""""""""" | BS Beplankung |  |  | 0 | 1113HWa0812812538 |  |  |  |  |  |  | 0 | AllplanAttributes - Sicherheitsklasse: -
 | H2 Ebene 0 | WI-STB | 1113Wa 0812902364 | yes |  | m² | Zimmer- und Holzbauarbeiten | Wand | Innenwand 1-Schalig | WI-STB |  |  | 0 | 1113HWa0812902361 | NEW |  |  | 0 |  |  | 0 | AllplanAttributes - Sicherheitsklasse: -
 | H2 Ebene 0 | WI-LB | 1113Wa 0812902366 | yes |  | m² | Trockenbauarbeiten | Wand | Innenwand 1-Schalig | WI-LB |  |  | 0 | 1113HWa0812902361 | NEW |  |  | 0 |  |  | 0 | AllplanAttributes - ash_W_Trockenbau_Qualitäten: 9; Sicherheitsklasse: -
 | H2 Ebene 0 | WI-STB | 1113Wa 0812443688 | yes |  | m² | Zimmer- und Holzbauarbeiten | Wand | Innenwand 1-Schalig | WI-STB |  |  | 0 | 1113HWa0812428694 |  |  |  | 0 |  |  | 0 | AllplanAttributes - Sicherheitsklasse: -
 | H2 Ebene 0 | WI-LB | 1113Wa 0812840607 | yes |  | m² | Trockenbauarbeiten | Wand | Innenwand 1-Schalig | WI-LB |  |  | 0 | 1113HWa0812428694 |  |  |  | 0 | AllplanAttributes - ash_W_Trockenbau_Qualitäten: 9; Sicherheitsklasse: -
 | H2 Ebene 0 | WI-STB | 1113Wa 0812437352 | yes |  | m² | Zimmer- und Holzbauarbeiten | Wand | Außenwand 1-Schalig | WI-STB |  |  | 0 | 1113HWa0812434408 | NEW |  |  | 0 |  |  | 0 | AllplanAttributes - Text1: Feinputz an Wandseite zum Speisewagenraum; Sicherheitsklasse: -
 | H2 Ebene 0 | WI-LB | 1113Wa 0814153860 | yes |  | m² | Trockenbauarbeiten | Wand | Außenwand 1-Schalig | WI-LB |  |  | 0 | 1113HWa0812434408 | OTHER |  |  | 0 | AllplanAttributes - ash_W_Trockenbau_Qualitäten: 9; Text1: Feinputz an Wandseite zum Speisewagenraum; Sicherheitsklasse: -
 | H2 Ebene 0 | WI-STB | 1113Wa 0812437354 | yes |  | m² | Zimmer- und Holzbauarbeiten | Wand | Außenwand 1-Schalig | WI-STB |  |  | 0 | 1113HWa0812428692 | NEW |  |  | 0 |  |  | 0 | AllplanAttributes - Text1: Feinputz an Wandseite zum Speisenwagenraum; Sicherheitsklasse: -
 | H2 Ebene 0 | WI-LB | 1113Wa 0814154028 | yes |  | m² | Trockenbauarbeiten | Wand | Außenwand 1-Schalig | WI-LB |  |  | 0 | 1113HWa0812428692 | OTHER |  |  | 0 | AllplanAttributes - ash_W_Trockenbau_Qualitäten: 9; Text1: Feinputz an Wandseite zum Speisenwagenraum; Sicherheitsklasse: -
 | H2 Ebene 0 | WI-STB | 1113Wa 0812437344 | yes |  | m² | Zimmer- und Holzbauarbeiten | Wand | Außenwand 1-Schalig | WI-STB |  |  | 0 | 1113HWa0812428691 |  |  |  | 0 |  |  | 0 | AllplanAttributes - Sicherheitsklasse: -
 | H2 Ebene 0 | WI-LB | 1113Wa 0812845633 | yes |  | m² | Trockenbauarbeiten | Wand | Außenwand 1-Schalig | WI-LB |  |  | 0 | 1113HWa0812428691 |  |  |  | 0 | AllplanAttributes - ash_W_Trockenbau_Qualitäten: 9; Sicherheitsklasse: -
 | H2 Ebene 0 | WI-LB | 1113Wa 0812840793 | yes |  | m² | Trockenbauarbeiten | Wand | Innenwand 1-Schalig | WI-LB |  |  | 0 | 1113HWa0812840791 |  |  |  | 0 | AllplanAttributes - ash_W_Trockenbau_Qualitäten: 9; Sicherheitsklasse: -
 | H2 Ebene 0 | WI-STB | 1113Wa 0812840813 | yes |  | m² | Zimmer- und Holzbauarbeiten | Wand | Innenwand 1-Schalig | WI-STB |  |  | 0 | 1113HWa0812840791 |  |  |  | 0 |  |  | 0 | AllplanAttributes - Sicherheitsklasse: -
 | H2 Ebene 0 | WI-STB | 1113Wa 0812437655 | yes |  | m² | Zimmer- und Holzbauarbeiten | Wand | Außenwand 1-Schalig | WI-STB |  |  | 0 | 1113HWa0812428688 | NEW |  |  | 0 |  |  | 0 | AllplanAttributes - Sicherheitsklasse: -
 | H2 Ebene 0 | WI-LB | 1113Wa 0812847543 | yes |  | m² | Trockenbauarbeiten | Wand | Außenwand 1-Schalig | WI-LB |  |  | 0 | 1113HWa0812428688 | NEW |  |  | 0 | AllplanAttributes - ash_W_Trockenbau_Qualitäten: 9; Sicherheitsklasse: -

# IfcWindow (393)
PartitioningType: USERDEFINED
Name | In | OverallHeight (m) | OverallWidth (m) | PredefinedType | AllplanAttributes (Fenster), V6 (m) = AllplanAttributes (Fenster), V7 (m) = AllplanAttributes (Fenster), V8 (m) = AllplanAttributes (Fenster), V9 = HeightWindowSillOutside = HeightWindowSillInside | AllplanAttributes (Fenster), Ortscode_Geschoßbezeichnung | AllplanAttributes (Fenster), Programmversion | AllplanAttributes (Fenster), Bezeichnung | AllplanAttributes (Fenster), Plugin_Bezeichnung | AllplanAttributes (Fenster), Plugin_Objektname | AllplanAttributes (Fenster), Glasanteil_berücksichtigen | AllplanAttributes (Fenster), Version | AllplanAttributes (Fenster), OKFF | ash T_Tür-Nr. | AllplanAttributes (Fenster), g-Wert | AllplanAttributes (Fenster), Attributset-Objekt | AllplanAttributes (Fenster), P_ID | AllplanAttributes (Fenster), Allright_Bauteil_ID | AllplanAttributes (Fenster), Abrechnungsart | AllplanAttributes (Fenster), Objektname | GlassSurface | OffsetOpeningBottom = OffsetOpeningTop = OffsetOpeningLeft = OffsetOpeningRight | DeductionOpeningBottom | DeductionOpeningLeft | DeductionOpeningRight | DeductionOpeningTop | FireRating | ThermalTransmittance (W/K/m2) | AcousticRating | SecurityRating | Reference | AllplanAttributes (Fenster), ash D_Detailverweis
Fenster | H2 Ebene +3 | 2.5 | 1.25 | WINDOW | 0 | E03 | 3.0 | Fenster | MainObject | SmartPartCompressed | 100 | 6.1 | 11.25 | FA-1FR-D-1S-E03-200b | 0,51 | Window | 1266Rau0000015498 | 1255Mak0811530992 | St | Fenstermakro, -SmartPart | 2.1694 | 0 | 70 | 70 | 70 | 70 | 0 | 0.9 | 32 | - | F_Typ4
Fenster | H2 Ebene +3 | 2.5 | 1.25 | WINDOW | 0 | E03 | 3.0 | Fenster | MainObject | SmartPartCompressed | 100 | 6.1 | 11.25 | FA-1FL-D-1S-E03-201b | 0,51 | Window | 1266Rau0000015498 | 1255Mak0811531460 | St | Fenstermakro, -SmartPart | 2.1694 | 0 | 70 | 70 | 70 | 70 | 0 | 0.9 | 32 | - | F_Typ3
Fenster | H2 Ebene +3 | 2.12 | 1.35 | WINDOW | 0 | E03 | 3.0 | Fenster | MainObject | SmartPartCompressed | 100 | 6.1 | 11.25 | FA-1FL-D-1S-E03-L143 | 0,35 | Window | 1265Rau0000000023 | 1255Mak0811534244 | St | Fenstermakro, -SmartPart | 2.0314 | 0 | 70 | 70 | 70 | 70 | 0 | 0.9 | - | - | F_Typ3A | Typ3A | AllplanAttributes (Fenster) - ash D_Plannummer: D1727
Fenster | H2 Ebene +3 | 2.12 | 1.35 | WINDOW | 0 | E03 | 3.0 | Fenster | MainObject | SmartPartCompressed | 100 | 6.1 | 11.25 | FA-1FL-D-1S-E03-L146 | 0,35 | Window | 1265Rau0000000023 | 1255Mak0811534431 | St | Fenstermakro, -SmartPart | 2.0314 | 0 | 70 | 70 | 70 | 70 | 0 | 0.9 | - | - | F_Typ3A | Typ3A | AllplanAttributes (Fenster) - ash D_Plannummer: D1727
Fenster | H2 Ebene +3 | 2.12 | 1.35 | WINDOW | 0 | E03 | 3.0 | Fenster | MainObject | SmartPartCompressed | 100 | 6.1 | 11.25 | FA-1FL-D-1S-E03-L146a | 0,35 | Window | 1265Rau0000000023 | 1255Mak0811534488 | St | Fenstermakro, -SmartPart | 2.0314 | 0 | 70 | 70 | 70 | 70 | 0 | 0.9 | - | - | F_Typ3A | Typ3A | AllplanAttributes (Fenster) - ash D_Plannummer: D1727
Fenster | H2 Ebene +3 | 2.12 | 1.35 | WINDOW | 0 | E03 | 3.0 | Fenster | MainObject | SmartPartCompressed | 100 | 6.1 | 11.25 | FA-1FL-D-1S-E03-L145 | 0,35 | Window | 1265Rau0000000023 | 1255Mak0811534374 | St | Fenstermakro, -SmartPart | 2.0314 | 0 | 70 | 70 | 70 | 70 | 0 | 0.9 | - | - | F_Typ3A | Typ3A | AllplanAttributes (Fenster) - ash D_Plannummer: D1727
Fenster | H2 Ebene +3 | 2.12 | 1.35 | WINDOW | 0 | E03 | 3.0 | Fenster | MainObject | SmartPartCompressed | 100 | 6.1 | 11.25 | FA-1FL-D-1S-E03-L144 | 0,35 | Window | 1265Rau0000000023 | 1255Mak0811534317 | St | Fenstermakro, -SmartPart | 2.0314 | 0 | 70 | 70 | 70 | 70 | 0 | 0.9 | - | - | F_Typ3A | Typ3A | AllplanAttributes (Fenster) - ash D_Plannummer: D1727
Fenster | H2 Ebene +3 | 2.12 | 1.35 | WINDOW | 0 | E03 | 3.0 | Fenster | MainObject | SmartPartCompressed | 100 | 6.1 | 11.25 | FA-1FL-D-1S-E03-L143a | 0,35 | Window | 1265Rau0000000023 | 1255Mak0811533862 | St | Fenstermakro, -SmartPart | 2.0314 | 0 | 70 | 70 | 70 | 70 | 0 | 0.9 | - | - | F_Typ3A | Typ3A | AllplanAttributes (Fenster) - ash D_Plannummer: D1727
Fenster | H2 Ebene +3 | 2.12 | 1.35 | WINDOW | 0 | E03 | 3.0 | Fenster | MainObject | SmartPartCompressed | 100 | 6.1 | 11.25 | FA-1FL-D-1S-E03-L154 | 0,35 | Window | 1265Rau0000000012 | 1255Mak0811537776 | St | Fenstermakro, -SmartPart | 2.0002 | 0 | 70 | 70 | 70 | 70 | 0 | 0.9 | - | - | F_Typ3A | Typ3A | AllplanAttributes (Fenster) - ash D_Plannummer: D1727
Fenster | H2 Ebene +3 | 2.12 | 1.35 | WINDOW | 0 | E03 | 3.0 | Fenster | MainObject | SmartPartCompressed | 100 | 6.1 | 11.25 | FA-1FL-D-1S-E03-L153 | 0,35 | Window | 1265Rau0000000012 | 1255Mak0811537692 | St | Fenstermakro, -SmartPart | 2.0002 | 0 | 70 | 70 | 70 | 70 | 0 | 0.9 | - | - | F_Typ3A | Typ3A | AllplanAttributes (Fenster) - ash D_Plannummer: D1727
Fenster | H2 Ebene +3 | 2.12 | 1.35 | WINDOW | 0 | E03 | 3.0 | Fenster | MainObject | SmartPartCompressed | 100 | 6.1 | 11.25 | FA-1FL-D-1S-E03-L148 | 0,35 | Window | 1265Rau0000000012 | 1255Mak0811535797 | St | Fenstermakro, -SmartPart | 2.0002 | 0 | 70 | 70 | 70 | 70 | 0 | 0.9 | - | - | F_Typ3A | Typ3A | AllplanAttributes (Fenster) - ash D_Plannummer: D1727
Fenster | H2 Ebene +3 | 2.12 | 1.35 | WINDOW | 0 | E03 | 3.0 | Fenster | MainObject | SmartPartCompressed | 100 | 6.1 | 11.25 | FA-1FL-D-1S-E03-L147 | 0,35 | Window | 1265Rau0000000012 | 1255Mak0811535658 | St | Fenstermakro, -SmartPart | 2.0002 | 0 | 70 | 70 | 70 | 70 | 0 | 0.9 | - | - | F_Typ3A | Typ3A | AllplanAttributes (Fenster) - ash D_Plannummer: D1727
Fenster | H2 Ebene +3 | 2.5 | 1.25 | WINDOW | 0 | E03 | 3.0 | Fenster | MainObject | SmartPartCompressed | 100 | 6.1 | 11.25 | FA-1FL-D-1S-E03-205b | 0,35 | Window | 1216Rau0000046703 | 1255Mak0811529591 | St | Fenstermakro, -SmartPart | 2.1694 | 0 | 70 | 70 | 70 | 70 | 0 | 0.9 | 32 | - | F_Typ3 | Typ 3 | AllplanAttributes (Fenster) - ash D_Plannummer: D1727; Sonnenschutztyp: Movable
Fenster | H2 Ebene +3 | 2.5 | 1.25 | WINDOW | 0 | E03 | 3.0 | Fenster | MainObject | SmartPartCompressed | 100 | 6.1 | 11.25 | FA-1FL-D-1S-E03-205a | 0,35 | Window | 1215Rau0000006938 | 1255Mak0811529512 | St | Fenstermakro, -SmartPart | 2.1694 | 0 | 70 | 70 | 70 | 70 | 0 | 0.9 | 32 | - | F_Typ3 | <undefiniert> | AllplanAttributes (Fenster) - Sonnenschutztyp: Movable
Fenster | H2 Ebene +3 | 2.5 | 3.92258 | WINDOW | 0 | E03 | 3.0 | Fenster | MainObject | SmartPartCompressed | 100 | 7.2 | 11.25 | FA-1FR-D-2S-E03-204b | 0,35 | Window | 1215Rau0000006911 | 1255Mak0811529487 | St | Fenstermakro, -SmartPart | 8.33749 | 0 | 70 | 70 | 70 | 70 | 0 | 0.9 | 32 | - | F_Typ29 | <undefiniert> | AllplanAttributes (Fenster) - Sonnenschutztyp: Movable
Fenster | H2 Ebene +3 | 2.5 | 1.65 | WINDOW | 0 | E03 | 3.0 | Fenster | MainObject | SmartPartCompressed | 100 | 6.1 | 11.25 | FA-1FR-D-1S-E03-204a | 0,35 | Window | 1215Rau0000006911 | 1255Mak0811529431 | St | Fenstermakro, -SmartPart | 3.0734 | 0 | 70 | 70 | 70 | 70 | 0 | 0.9 | 32 | - | F_Typ28 | <undefiniert> | AllplanAttributes (Fenster) - Sonnenschutztyp: Movable
Fenster | H2 Ebene +3 | 2.5 | 1.25 | WINDOW | 0 | E03 | 3.0 | Fenster | MainObject | SmartPartCompressed | 100 | 6.1 | 11.25 | FA-1FL-D-1S-E03-203b | 0,35 | Window | 1216Rau0000046767 | 1255Mak0811529381 | St | Fenstermakro, -SmartPart | 2.1694 | 0 | 70 | 70 | 70 | 70 | 0 | 0.9 | 32 | - | F_Typ3 | Typ 3 | AllplanAttributes (Fenster) - ash D_Plannummer: D1727; Sonnenschutztyp: Movable
Fenster | H2 Ebene +3 | 2.5 | 1.25 | WINDOW | 0 | E02 | 3.0 | Fenster | MainObject | SmartPartCompressed | 100 | 6.1 | 11.25 | FA-1FL-D-1S-E03-203a | 0,35 | Window | 1216Rau0000046781 | 1255Mak0811529325 | St | Fenstermakro, -SmartPart | 2.1694 | 0 | 70 | 70 | 70 | 70 | 0 | 0.9 | 32 | - | F_Typ3 | Typ 3 | AllplanAttributes (Fenster) - ash D_Plannummer: D1727; Sonnenschutztyp: Movable
Fenster | H2 Ebene +3 | 1.25 | 2.5 | WINDOW | 0 | E03 | 3.0 | Fenster | MainObject | SmartPartCompressed | 100 | 6.1 | 11.25 | FA-ZG-E03-L141 | - | Window | 1266Rau0000012892 | 1255Mak0000004563 | St | Fenstermakro, -SmartPart | 0 | 0 | 70 | 70 | 70 | 70 | 0 | 0 | - | - | F_Typ40
Fenster | H2 Ebene +3 | 1.25 | 2.5 | WINDOW | 0 | E03 | 3.0 | Fenster | MainObject | SmartPartCompressed | 100 | 6.1 | 11.25 | FA-ZG-E03-L156 | - | Window | 1266Rau0000012920 | 1255Mak0000002082 | St | Fenstermakro, -SmartPart | 0 | 0 | 70 | 70 | 70 | 70 | 0 | 0 | - | - | F_Typ40
Fenster | H2 Ebene +3 | 2.12 | 1.35 | WINDOW | 0 | E03 | 3.0 | Fenster | MainObject | SmartPartCompressed | 100 | 6.1 | 11.25 | FA-1FL-D-1S-E03-L151 | 0,35 | Window | 1265Rau0000000012 | 1255Mak0811537525 | St | Fenstermakro, -SmartPart | 2.0002 | 0 | 70 | 70 | 70 | 70 | 0 | 0.9 | - | - | F_Typ3A | Typ3A | AllplanAttributes (Fenster) - ash D_Plannummer: D1727
Fenster | H2 Ebene +3 | 1.115 | 2.3945 | WINDOW | 0 |  | 2.2 | Fenster | MainObject | SmartPartCompressed | 100 | 4.1 |  |  |  |  |  | 1255Mak0811497989 | St | Fenstermakro, -SmartPart | 2.26313 | 0 | 60 | 60 | 60 | 60 |  | 0 |  |  | Codetext | AllplanAttributes (Fenster) - Codetext: Codetext; Gewerk: Metallbau-, Schlosserarbeiten; Funktion: Funktion; Glasart: Glasart; Typ: Typ; Fluchtweg: no; Pset_DoorWindowGlazingType - Shading Coefficient: 0; Pset_WindowCommon - Status: NEW; IsExternal: yes; SmokeStop: no
Fenster | H2 Ebene +3 | 1.115 | 2.418 | WINDOW | 0 |  | 2.2 | Fenster | MainObject | SmartPartCompressed | 100 | 4.1 |  |  |  |  |  | 1255Mak0811498468 | St | Fenstermakro, -SmartPart | 2.28651 | 0 | 60 | 60 | 60 | 60 |  | 0 |  |  | Codetext | AllplanAttributes (Fenster) - Codetext: Codetext; Gewerk: Metallbau-, Schlosserarbeiten; Funktion: Funktion; Glasart: Glasart; Typ: Typ; Fluchtweg: no; Pset_DoorWindowGlazingType - Shading Coefficient: 0; Pset_WindowCommon - Status: NEW; IsExternal: yes; SmokeStop: no
Symbol BD | H2 Ebene +3 | 0.45 | 0.45 | SKYLIGHT |  |  |  |  |  |  |  |  |  |  |  |  |  |  |  |  |  |  |  |  |  |  | 0 | 0.9 | 32 | - | AllplanAttributes (Symbol BD) - V6: 0 m; V7: 0 m; V8: 0 m; V9: 0; Programmversion: 3.0; Objektname: Bodendurchbruchsmakro; Bezeichnung: Symbol BD; Plugin_Bezeichnung: MainObject; Plugin_Objektname: SmartPartCompressed; Version: 1.0; Sonnenschutztyp: Movable; g-Wert: 0,51; Attributset-Objekt: Opening; Allright_Bauteil_ID: 1264Mak0813471683; Abrechnungsart: St
Symbol BD | H2 Ebene +3 | 0.45 | 0.45 | SKYLIGHT |  |  |  |  |  |  |  |  |  |  |  |  |  |  |  |  |  |  |  |  |  |  | 0 | 0.9 | 32 | - | AllplanAttributes (Symbol BD) - V6: 0 m; V7: 0 m; V8: 0 m; V9: 0; Programmversion: 3.0; Objektname: Bodendurchbruchsmakro; Bezeichnung: Symbol BD; Plugin_Bezeichnung: MainObject; Plugin_Objektname: SmartPartCompressed; Version: 1.0; Sonnenschutztyp: Movable; g-Wert: 0,51; Attributset-Objekt: Opening; Allright_Bauteil_ID: 1264Mak0813471674; Abrechnungsart: St
Fenster | H2 Ebene +2 | 2.12 | 0.725 | WINDOW | 0 | E02 | 3.0 | Fenster | MainObject | SmartPartCompressed | 100 | 6.1 | 7.5 | FA-F-E02-L099 | 0,35 | Window | 1216Rau0000046405 | 1205Mak0000281483 | St | Fenstermakro, -SmartPart | 1.0998 | 0 | 70 | 70 | 70 | 70 | 0 | 0.9 | 32 | - | F_Typ6 | <undefiniert> | AllplanAttributes (Fenster) - Sonnenschutztyp: Movable
Fenster | H2 Ebene +2 | 2.12 | 1.35 | WINDOW | 0 | E02 | 3.0 | Fenster | MainObject | SmartPartCompressed | 100 | 6.1 | 7.5 | FA-1FR-D-1S-E02-L093 | 0,35 | Window | 1216Rau0000046447 | 1205Mak0000281560 | St | Fenstermakro, -SmartPart | 2.0002 | 0 | 70 | 70 | 70 | 70 | 0 | 0.9 | 32 | - | F_Typ4A | <undefiniert> | AllplanAttributes (Fenster) - Sonnenschutztyp: Movable
Fenster | H2 Ebene +2 | 2.12 | 1.35 | WINDOW | 0 | E02 | 3.0 | Fenster | MainObject | SmartPartCompressed | 100 | 6.1 | 7.5 | FA-1FR-D-1S-E02-L095 | 0,35 | Window | 1216Rau0000046433 | 1205Mak0000281537 | St | Fenstermakro, -SmartPart | 2.0002 | 0 | 70 | 70 | 70 | 70 | 0 | 0.9 | 32 | - | F_Typ4A | <undefiniert> | AllplanAttributes (Fenster) - Sonnenschutztyp: Movable
Fenster | H2 Ebene +2 | 2.12 | 0.725 | WINDOW | 0 | E02 | 3.0 | Fenster | MainObject | SmartPartCompressed | 100 | 6.1 | 7.5 | FA-F-E02-L096 | 0,35 | Window | 1216Rau0000046419 | 1205Mak0000281476 | St | Fenstermakro, -SmartPart | 1.0998 | 0 | 70 | 70 | 70 | 70 | 0 | 0.9 | 32 | - | F_Typ6 | <undefiniert> | AllplanAttributes (Fenster) - Sonnenschutztyp: Movable
Fenster | H2 Ebene +2 | 2.12 | 1.35 | WINDOW | 0 | E02 | 3.0 | Fenster | MainObject | SmartPartCompressed | 100 | 6.1 | 7.5 | FA-1FR-D-1S-E02-L098 | 0,35 | Window | 1216Rau0000046405 | 1205Mak0000281465 | St | Fenstermakro, -SmartPart | 2.0002 | 0 | 70 | 70 | 70 | 70 | 0 | 0.9 | 32 | - | F_Typ4A | <undefiniert> | AllplanAttributes (Fenster) - Sonnenschutztyp: Movable
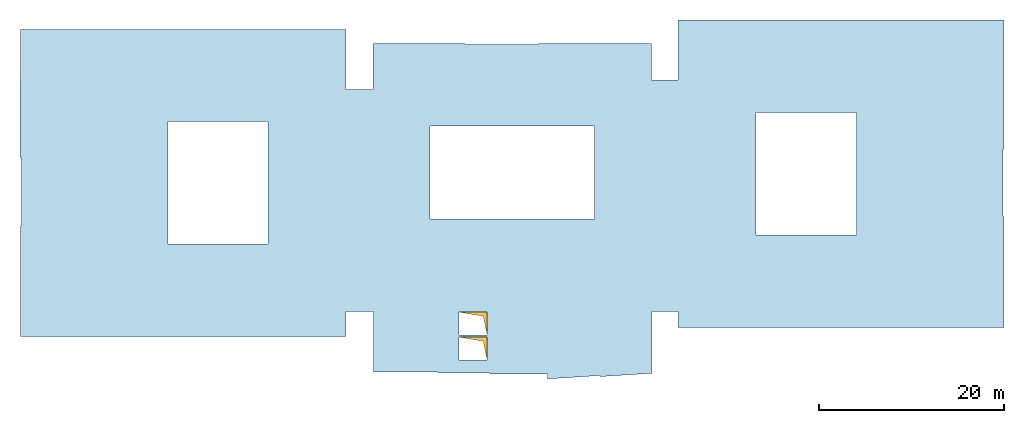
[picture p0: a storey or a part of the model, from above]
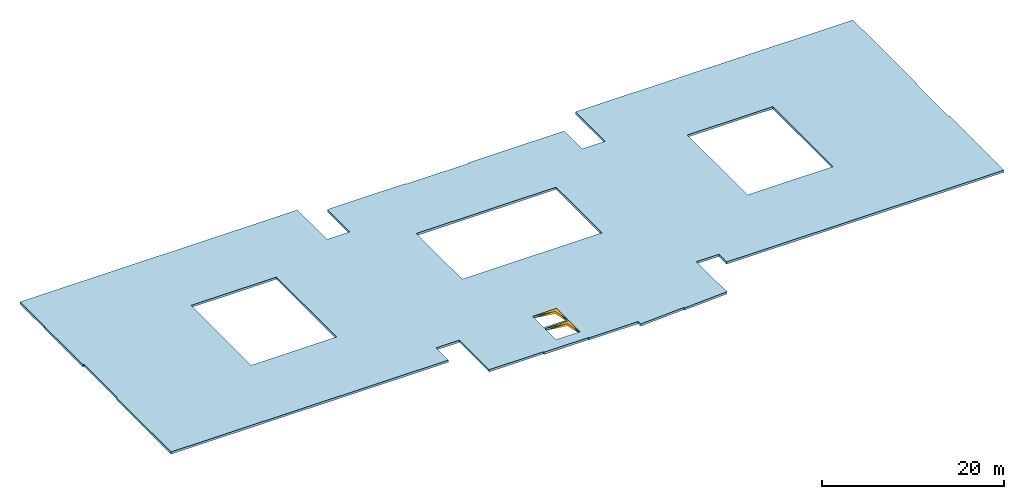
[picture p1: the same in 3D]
Properties of the parts of a building model (IFC4), part 78 of 80

# IfcWindow (393)
Name | In | OverallHeight (m) | OverallWidth (m) | PredefinedType | AllplanAttributes (Fenster), V6 (m) = AllplanAttributes (Fenster), V7 (m) = AllplanAttributes (Fenster), V8 (m) = AllplanAttributes (Fenster), V9 = HeightWindowSillOutside = HeightWindowSillInside | AllplanAttributes (Fenster), Ortscode_Geschoßbezeichnung | AllplanAttributes (Fenster), Programmversion | AllplanAttributes (Fenster), Bezeichnung | AllplanAttributes (Fenster), Plugin_Bezeichnung | AllplanAttributes (Fenster), Plugin_Objektname | AllplanAttributes (Fenster), Glasanteil_berücksichtigen | AllplanAttributes (Fenster), Version | AllplanAttributes (Fenster), OKFF | ash T_Tür-Nr. | AllplanAttributes (Fenster), g-Wert | AllplanAttributes (Fenster), Attributset-Objekt | AllplanAttributes (Fenster), P_ID | AllplanAttributes (Fenster), Allright_Bauteil_ID | AllplanAttributes (Fenster), Abrechnungsart | AllplanAttributes (Fenster), Objektname | GlassSurface | OffsetOpeningBottom = OffsetOpeningTop = OffsetOpeningLeft = OffsetOpeningRight | DeductionOpeningBottom | DeductionOpeningLeft | DeductionOpeningRight | DeductionOpeningTop | FireRating | ThermalTransmittance (W/K/m2) | AcousticRating | SecurityRating | Reference | AllplanAttributes (Fenster), ash D_Detailverweis
Fenster | H2 Ebene +2 | 2.12 | 1.35 | WINDOW | 0 | E02 | 3.0 | Fenster | MainObject | SmartPartCompressed | 100 | 6.1 | 7.5 | FA-1FR-D-1S-E02-L097 | 0,35 | Window | 1216Rau0000046419 | 1205Mak0000281504 | St | Fenstermakro, -SmartPart | 2.0002 | 0 | 70 | 70 | 70 | 70 | 0 | 0.9 | 32 | - | F_Typ4A | <undefiniert> | AllplanAttributes (Fenster) - Sonnenschutztyp: Movable
Fenster | H2 Ebene +2 | 2.5 | 2.5 | WINDOW | 0 | E02 | 3.0 | Fenster | MainObject | SmartPartCompressed | 100 | 6.1 | 7.5 | FA-1FL-D-1S-X-E02-190 | 0,51 | Window | 1216Rau0000046367 | 1205Mak0000281361 | St | Fenstermakro, -SmartPart | 4.9494 | 0 | 70 | 70 | 70 | 70 | 0 | 0.9 | 39 | - | F_Typ1 | Typ 1 | AllplanAttributes (Fenster) - ash D_Plannummer: D1726; Sonnenschutztyp: Movable
Fenster | H2 Ebene +2 | 2.5 | 2.5 | WINDOW | 0 | E02 | 3.0 | Fenster | MainObject | SmartPartCompressed | 100 | 6.1 | 7.5 | FA-1FR-D-1S-X-E02-181 | 0,51 | Window | 1216Rau0000046883 | 1205Mak0000281660 | St | Fenstermakro, -SmartPart | 4.9494 | 0 | 70 | 70 | 70 | 70 | 0 | 0.9 | 35 | - | F_Typ2 | <undefiniert> | AllplanAttributes (Fenster) - Sonnenschutztyp: Movable
Fenster | H2 Ebene +2 | 2.5 | 2.5 | WINDOW | 0 | E02 | 3.0 | Fenster | MainObject | SmartPartCompressed | 100 | 6.1 | 7.5 | FA-1FL-D-1S-X-E02-178 | 0,51 | Window | 1216Rau0000046987 | 1205Mak0000281438 | St | Fenstermakro, -SmartPart | 4.9494 | 0 | 70 | 70 | 70 | 70 | 0 | 0.9 | 35 | - | F_Typ1 | Typ 1 | AllplanAttributes (Fenster) - ash D_Plannummer: D1726; Sonnenschutztyp: Movable
Fenster | H2 Ebene +2 | 2.5 | 2.5 | WINDOW | 0 | E02 | 3.0 | Fenster | MainObject | SmartPartCompressed | 100 | 6.1 | 7.5 | FA-1FR-D-1S-X-E02-177 | 0,51 | Window | 1216Rau0000047025 | 1205Mak0000281625 | St | Fenstermakro, -SmartPart | 4.9494 | 0 | 70 | 70 | 70 | 70 | 0 | 0.9 | 35 | - | F_Typ2 | <undefiniert> | AllplanAttributes (Fenster) - Sonnenschutztyp: Movable
Fenster | H2 Ebene +2 | 2.5 | 2.5 | WINDOW | 0 | E02 | 3.0 | Fenster | MainObject | SmartPartCompressed | 100 | 6.1 | 7.5 | FA-1FL-D-1S-X-E02-176 | 0,51 | Window | 1216Rau0000047039 | 1205Mak0000281621 | St | Fenstermakro, -SmartPart | 4.9494 | 0 | 70 | 70 | 70 | 70 | 0 | 0.9 | 35 | - | F_Typ1 | Typ 1 | AllplanAttributes (Fenster) - ash D_Plannummer: D1726; Sonnenschutztyp: Movable
Fenster | H2 Ebene +2 | 2.5 | 2.5 | WINDOW | 0 | E02 | 3.0 | Fenster | MainObject | SmartPartCompressed | 100 | 6.1 | 7.5 | FA-1FR-D-1S-X-E02-175 | 0,51 | Window | 1216Rau0000047077 | 1205Mak0000281479 | St | Fenstermakro, -SmartPart | 4.9494 | 0 | 70 | 70 | 70 | 70 | 0 | 0.9 | 35 | - | F_Typ2 | <undefiniert> | AllplanAttributes (Fenster) - Sonnenschutztyp: Movable
Fenster | H2 Ebene +2 | 2.5 | 2.5 | WINDOW | 0 | E02 | 3.0 | Fenster | MainObject | SmartPartCompressed | 100 | 6.1 | 7.5 | FA-1FL-D-1S-X-E02-192 | 0,51 | Window | 1216Rau0000046315 | 1205Mak0000281369 | St | Fenstermakro, -SmartPart | 4.9494 | 0 | 70 | 70 | 70 | 70 | 0 | 0.9 | 39 | - | F_Typ1 | Typ 1 | AllplanAttributes (Fenster) - ash D_Plannummer: D1726; Sonnenschutztyp: Movable
Fenster | H2 Ebene +2 | 2.5 | 2.5 | WINDOW | 0 | E02 | 3.0 | Fenster | MainObject | SmartPartCompressed | 100 | 6.1 | 7.5 | FA-1FR-D-1S-X-E02-191 | 0,51 | Window | 1216Rau0000046353 | 1205Mak0000281373 | St | Fenstermakro, -SmartPart | 4.9494 | 0 | 70 | 70 | 70 | 70 | 0 | 0.9 | 39 | - | F_Typ2 | <undefiniert> | AllplanAttributes (Fenster) - Sonnenschutztyp: Movable
Fenster | H2 Ebene +2 | 2.5 | 2.5 | WINDOW | 0 | E02 | 3.0 | Fenster | MainObject | SmartPartCompressed | 100 | 6.1 | 7.5 | FA-1FL-D-1S-X-E02-194 | 0,51 | Window | 1216Rau0000046263 | 1205Mak0000281365 | St | Fenstermakro, -SmartPart | 4.9494 | 0 | 70 | 70 | 70 | 70 | 0 | 0.9 | 42 | - | F_Typ1 | Typ 1 | AllplanAttributes (Fenster) - ash D_Plannummer: D1726; Sonnenschutztyp: Movable
Fenster | H2 Ebene +2 | 2.5 | 2.5 | WINDOW | 0 | E02 | 3.0 | Fenster | MainObject | SmartPartCompressed | 100 | 6.1 | 7.5 | FA-1FR-D-1S-X-E02-193 | 0,51 | Window | 1216Rau0000046301 | 1205Mak0000281357 | St | Fenstermakro, -SmartPart | 4.9494 | 0 | 70 | 70 | 70 | 70 | 0 | 0.9 | 42 | - | F_Typ2 | <undefiniert> | AllplanAttributes (Fenster) - Sonnenschutztyp: Movable
Fenster | H2 Ebene +2 | 2.5 | 1.25 | WINDOW | 0 | E02 | 3.0 | Fenster | MainObject | SmartPartCompressed | 100 | 6.1 | 7.5 | FA-1FL-D-1S-E02-160 | 0,51 | Window | 1216Rau0000047209 | 1205Mak0000281575 | St | Fenstermakro, -SmartPart | 2.1674 | 0 | 70 | 70 | 70 | 70 | 0 | 0.9 | 32 | - | F_Typ3 | Typ 3 | AllplanAttributes (Fenster) - ash D_Plannummer: D1727; Sonnenschutztyp: Movable
Fenster | H2 Ebene +2 | 2.5 | 2.5 | WINDOW | 0 | E02 | 3.0 | Fenster | MainObject | SmartPartCompressed | 100 | 6.1 | 7.5 | FA-1FL-D-1S-X-E02-169 | 0,51 | Window | 1216Rau0000047365 | 1205Mak0000281590 | St | Fenstermakro, -SmartPart | 4.9494 | 0 | 70 | 70 | 70 | 70 | 0 | 0.9 | 32 | - | F_Typ1 | Typ 1 | AllplanAttributes (Fenster) - ash D_Plannummer: D1726; Sonnenschutztyp: Movable
Fenster | H2 Ebene +2 | 2.5 | 2.5 | WINDOW | 0 | E02 | 3.0 | Fenster | MainObject | SmartPartCompressed | 100 | 6.1 | 7.5 | FA-1FR-D-1S-X-E02-168 | 0,51 | Window | 1216Rau0000047339 | 1205Mak0000281656 | St | Fenstermakro, -SmartPart | 4.9494 | 0 | 70 | 70 | 70 | 70 | 0 | 0.9 | 32 | - | F_Typ2 | <undefiniert> | AllplanAttributes (Fenster) - Sonnenschutztyp: Movable
Fenster | H2 Ebene +2 | 2.5 | 2.5 | WINDOW | 0 | E02 | 3.0 | Fenster | MainObject | SmartPartCompressed | 100 | 6.1 | 7.5 | FA-1FL-D-1S-X-E02-171 | 0,51 | Window | 1216Rau0000047417 | 1205Mak0000281594 | St | Fenstermakro, -SmartPart | 4.9494 | 0 | 70 | 70 | 70 | 70 | 0 | 0.9 | 32 | - | F_Typ1 | Typ 1 | AllplanAttributes (Fenster) - ash D_Plannummer: D1726; Sonnenschutztyp: Movable
Fenster | H2 Ebene +2 | 2.5 | 2.5 | WINDOW | 0 | E02 | 3.0 | Fenster | MainObject | SmartPartCompressed | 100 | 6.1 | 7.5 | FA-1FR-D-1S-X-E02-170 | 0,51 | Window | 1216Rau0000047391 | 1205Mak0000281529 | St | Fenstermakro, -SmartPart | 4.9494 | 0 | 70 | 70 | 70 | 70 | 0 | 0.9 | 32 | - | F_Typ2 | <undefiniert> | AllplanAttributes (Fenster) - Sonnenschutztyp: Movable
Fenster | H2 Ebene +2 | 2.5 | 2.28 | WINDOW | 0 | E02 | 3.0 | Fenster | MainObject | SmartPartCompressed | 100 | 6.1 | 7.5 | FA-1FL-D-1S-X-E02-172 | 0,35 | Window | 1215Rau0000006914 | 1205Mak0000281442 | St | Fenstermakro, -SmartPart | 4.4972 | 0 | 70 | 70 | 70 | 70 | 0 | 0.9 | 32 | - | F_Typ38 | <undefiniert> | AllplanAttributes (Fenster) - Gewerk: Fensterarbeiten; Pset_WindowCommon - Status: NEW; IsExternal: yes
Fenster | H2 Ebene +2 | 2.5 | 2.28 | WINDOW | 0 | E02 | 3.0 | Fenster | MainObject | SmartPartCompressed | 100 | 6.1 | 7.5 | FA-1FR-D-1S-X-E02-174 | 0,35 | Window | 1215Rau0000006893 | 1205Mak0000281692 | St | Fenstermakro, -SmartPart | 4.4972 | 0 | 70 | 70 | 70 | 70 | 0 | 0.9 | 32 | - | F_Typ7 | <undefiniert> | AllplanAttributes (Fenster) - Gewerk: Fensterarbeiten; Pset_WindowCommon - Status: NEW; IsExternal: yes
Fenster | H2 Ebene +2 | 2.12 | 1.35 | WINDOW | 0 | E02 | 3.0 | Fenster | MainObject | SmartPartCompressed | 100 | 6.1 | 7.5 | FA-1FL-D-1S-E02-L101 | 0,35 | Window | 1216Rau0000046125 | 1205Mak0000281579 | St | Fenstermakro, -SmartPart | 2.0002 | 0 | 70 | 70 | 70 | 70 | 0 | 0.9 | 32 | - | F_Typ3A | Typ 3 | AllplanAttributes (Fenster) - ash D_Plannummer: D1727; Sonnenschutztyp: Movable
Fenster | H2 Ebene +2 | 2.12 | 1.35 | WINDOW | 0 | E02 | 3.0 | Fenster | MainObject | SmartPartCompressed | 100 | 6.1 | 7.5 | FA-1FL-D-1S-E02-L103 | 0,35 | Window | 1216Rau0000047619 | 1205Mak0000281519 | St | Fenstermakro, -SmartPart | 2.0002 | 0 | 70 | 70 | 70 | 70 | 0 | 0.9 | 32 | - | F_Typ3A | Typ 3 | AllplanAttributes (Fenster) - ash D_Plannummer: D1727; Sonnenschutztyp: Movable
Fenster | H2 Ebene +2 | 2.12 | 1.35 | WINDOW | 0 | E02 | 3.0 | Fenster | MainObject | SmartPartCompressed | 100 | 6.1 | 7.5 | FA-1FL-D-1S-E02-L107 | 0,35 | Window | 1216Rau0000046083 | 1205Mak0000344968 | St | Fenstermakro, -SmartPart | 2.0002 | 0 | 70 | 70 | 70 | 70 | 0 | 0.9 | 32 | - | F_Typ3A | Typ 3 | AllplanAttributes (Fenster) - ash D_Plannummer: D1727; Sonnenschutztyp: Movable
Fenster | H2 Ebene +2 | 2.12 | 1.35 | WINDOW | 0 | E02 | 3.0 | Fenster | MainObject | SmartPartCompressed | 100 | 6.1 | 7.5 | FA-1FL-D-1S-E02-L106 | 0,35 | Window | 1216Rau0000046097 | 1205Mak0000281629 | St | Fenstermakro, -SmartPart | 2.0002 | 0 | 70 | 70 | 70 | 70 | 0 | 0.9 | 32 | - | F_Typ3A | Typ 3 | AllplanAttributes (Fenster) - ash D_Plannummer: D1727; Sonnenschutztyp: Movable
Fenster | H2 Ebene +2 | 2.12 | 1.35 | WINDOW | 0 | E02 | 3.0 | Fenster | MainObject | SmartPartCompressed | 100 | 6.1 | 7.5 | FA-1FL-D-1S-E02-L102 | 0,35 | Window | 1216Rau0000046111 | 1205Mak0000281526 | St | Fenstermakro, -SmartPart | 2.0002 | 0 | 70 | 70 | 70 | 70 | 0 | 0.9 | 32 | - | F_Typ3A | Typ 3 | AllplanAttributes (Fenster) - ash D_Plannummer: D1727; Sonnenschutztyp: Movable
Fenster | H2 Ebene +2 | 2.12 | 1.35 | WINDOW | 0 | E02 | 3.0 | Fenster | MainObject | SmartPartCompressed | 100 | 6.1 | 7.5 | FA-1FR-D-1S-E02-L120 | 0,35 | Window | 1216Rau0000046587 | 1205Mak0000356123 | St | Fenstermakro, -SmartPart | 2.0002 | 0 | 70 | 70 | 70 | 70 | 0 | 0.9 | - | - | F_Typ4A | AllplanAttributes (Fenster) - Sonnenschutztyp: Movable
Fenster | H2 Ebene +2 | 2.12 | 1.35 | WINDOW | 0 | E02 | 3.0 | Fenster | MainObject | SmartPartCompressed | 100 | 6.1 | 7.5 | FA-1FL-D-1S-E02-L114 | 0,35 | Window | 1216Rau0000047157 | 1205Mak2005819493 | St | Fenstermakro, -SmartPart | 2.0002 | 0 | 70 | 70 | 70 | 70 | 0 | 0.9 | - | - | F_Typ3A | Typ 3 | AllplanAttributes (Fenster) - ash D_Plannummer: D1727; Sonnenschutztyp: Movable
Fenster | H2 Ebene +2 | 2.12 | 1.35 | WINDOW | 0 | E02 | 3.0 | Fenster | MainObject | SmartPartCompressed | 100 | 6.1 | 7.5 | FA-1FL-D-1S-E02-L112 | 0,35 | Window | 1216Rau0000047157 | 1205Mak2005818697 | St | Fenstermakro, -SmartPart | 2.0002 | 0 | 70 | 70 | 70 | 70 | 0 | 0.9 | - | - | F_Typ3A | Typ 3 | AllplanAttributes (Fenster) - ash D_Plannummer: D1727; Sonnenschutztyp: Movable
Fenster | H2 Ebene +2 | 2.12 | 1.35 | WINDOW | 0 | E02 | 3.0 | Fenster | MainObject | SmartPartCompressed | 100 | 6.1 | 7.5 | FA-1FL-D-1S-E02-L113 | 0,35 | Window | 1216Rau0000047157 | 1205Mak2005819361 | St | Fenstermakro, -SmartPart | 2.0002 | 0 | 70 | 70 | 70 | 70 | 0 | 0.9 | - | - | F_Typ3A | Typ 3 | AllplanAttributes (Fenster) - ash D_Plannummer: D1727; Sonnenschutztyp: Movable
Fenster | H2 Ebene +2 | 2.12 | 2.6 | WINDOW | 0 | E02 | 3.0 | Fenster | MainObject | SmartPartCompressed | 100 | 6.1 | 7.5 | FA-2FLR-D-1S-E02-L117 | 0,35 | Window | 1216Rau0000046083 | 1205Mak2005823997 | St | Fenstermakro, -SmartPart | 4.0812 | 0 | 70 | 70 | 70 | 70 | 0 | 0.9 | 32 | - | Typ 44 | AllplanAttributes (Fenster) - Sonnenschutztyp: Movable
Fenster | H2 Ebene +2 | 2.12 | 1.35 | WINDOW | 0 | E02 | 3.0 | Fenster | MainObject | SmartPartCompressed | 100 | 6.1 | 7.5 | FA-1FR-D-1S-E02-L135 | 0,35 | Window | 1216Rau0000047105 | 1205Mak0000281507 | St | Fenstermakro, -SmartPart | 2.0002 | 0 | 70 | 70 | 70 | 70 | 0 | 0.9 | 32 | - | F_Typ4A | <undefiniert> | AllplanAttributes (Fenster) - Sonnenschutztyp: Movable
Fenster | H2 Ebene +2 | 2.12 | 1.35 | WINDOW | 0 | E02 | 3.0 | Fenster | MainObject | SmartPartCompressed | 100 | 6.1 | 7.5 | FA-1FR-D-1S-E02-L133 | 0,35 | Window | 1216Rau0000047091 | 1205Mak0000281664 | St | Fenstermakro, -SmartPart | 2.0002 | 0 | 70 | 70 | 70 | 70 | 0 | 0.9 | 32 | - | F_Typ4A | <undefiniert> | AllplanAttributes (Fenster) - Sonnenschutztyp: Movable
Fenster | H2 Ebene +2 | 2.12 | 0.725 | WINDOW | 0 | E02 | 3.0 | Fenster | MainObject | SmartPartCompressed | 100 | 6.1 | 7.5 | FA-F-E02-L131 | 0,35 | Window | 1216Rau0000046973 | 1205Mak0000281511 | St | Fenstermakro, -SmartPart | 1.0998 | 0 | 70 | 70 | 70 | 70 | 0 | 0.9 | 32 | - | F_Typ6 | <undefiniert> | AllplanAttributes (Fenster) - Sonnenschutztyp: Movable
Fenster | H2 Ebene +2 | 2.12 | 1.35 | WINDOW | 0 | E02 | 3.0 | Fenster | MainObject | SmartPartCompressed | 100 | 6.1 | 7.5 | FA-1FR-D-1S-E02-L132 | 0,35 | Window | 1216Rau0000046973 | 1205Mak0000281640 | St | Fenstermakro, -SmartPart | 2.0002 | 0 | 70 | 70 | 70 | 70 | 0 | 0.9 | 32 | - | F_Typ4A | <undefiniert> | AllplanAttributes (Fenster) - Sonnenschutztyp: Movable
Fenster | H2 Ebene +2 | 2.12 | 1.35 | WINDOW | 0 | E02 | 3.0 | Fenster | MainObject | SmartPartCompressed | 100 | 6.1 | 7.5 | FA-1FR-D-1S-E02-L136 | 0,35 | Window | 1216Rau0000047131 | 1205Mak0000281556 | St | Fenstermakro, -SmartPart | 2.0002 | 0 | 70 | 70 | 70 | 70 | 0 | 0.9 | 32 | - | F_Typ4A | <undefiniert> | AllplanAttributes (Fenster) - Sonnenschutztyp: Movable
Fenster | H2 Ebene +2 | 2.12 | 0.725 | WINDOW | 0 | E02 | 3.0 | Fenster | MainObject | SmartPartCompressed | 100 | 6.1 | 7.5 | FA-F-E02-L134 | 0,35 | Window | 1216Rau0000047091 | 1205Mak0000281563 | St | Fenstermakro, -SmartPart | 1.0998 | 0 | 70 | 70 | 70 | 70 | 0 | 0.9 | 32 | - | F_Typ6 | <undefiniert> | AllplanAttributes (Fenster) - Sonnenschutztyp: Movable
Fenster | H2 Ebene +2 | 2.5 | 1.5 | WINDOW | 0 | E02 | 3.0 | Fenster | MainObject | SmartPartCompressed | 100 | 6.1 | 7.5 | FA-1FL-D-1S-E02-173 | 0,35 | Window | 1215Rau0000006908 | 1205Mak0000281390 | St | Fenstermakro, -SmartPart | 2.7344 | 0 | 70 | 70 | 70 | 70 | 0 | 0.9 | - | - | F_Typ28 | <undefiniert> | AllplanAttributes (Fenster) - Sonnenschutztyp: Movable
Fenster | H2 Ebene +2 | 2.5 | 1.25 | WINDOW | 0 | E02 | 3.0 | Fenster | MainObject | SmartPartCompressed | 100 | 6.1 | 7.5 | FA-1FR-D-1S-E02-187 | 0,35 | Window | 1215Rau0000006938 | 1205Mak0000281490 | St | Fenstermakro, -SmartPart | 2.1694 | 0 | 70 | 70 | 70 | 70 | 0 | 0.9 | 32 | - | F_Typ4 | <undefiniert> | AllplanAttributes (Fenster) - Sonnenschutztyp: Movable
Fenster | H2 Ebene +2 | 2.5 | 1.25 | WINDOW | 0 | E02 | 3.0 | Fenster | MainObject | SmartPartCompressed | 100 | 6.1 | 7.5 | FA-1FR-D-1S-E02-188 | 0,35 | Window | 1216Rau0000046703 | 1205Mak0000281668 | St | Fenstermakro, -SmartPart | 2.1694 | 0 | 70 | 70 | 70 | 70 | 0 | 0.9 | 32 | - | F_Typ4 | AllplanAttributes (Fenster) - Sonnenschutztyp: Movable
Fenster | H2 Ebene +2 | 2.12 | 1.35 | WINDOW | 0 | E02 | 3.0 | Fenster | MainObject | SmartPartCompressed | 100 | 6.1 | 7.5 | FA-1FL-D-1S-E02-L119 | 0,35 | Window | 1216Rau0000047157 | 1205Mak2005824596 | St | Fenstermakro, -SmartPart | 2.0002 | 0 | 70 | 70 | 70 | 70 | 0 | 0.9 | - | - | F_Typ3A | Typ 3 | AllplanAttributes (Fenster) - ash D_Plannummer: D1727; Sonnenschutztyp: Movable
Fenster | H2 Ebene +2 | 2.12 | 1.35 | WINDOW | 0 | E02 | 3.0 | Fenster | MainObject | SmartPartCompressed | 100 | 6.1 | 7.5 | FA-1FL-D-1S-E02-L118 | 0,35 | Window | 1216Rau0000047157 | 1205Mak2005824498 | St | Fenstermakro, -SmartPart | 2.0002 | 0 | 70 | 70 | 70 | 70 | 0 | 0.9 | - | - | F_Typ3A | Typ 3 | AllplanAttributes (Fenster) - ash D_Plannummer: D1727; Sonnenschutztyp: Movable
Fenster | H2 Ebene +2 | 2.12 | 1.35 | WINDOW | 0 | E02 | 3.0 | Fenster | MainObject | SmartPartCompressed | 100 | 6.1 | 7.5 | FA-1FL-D-1S-E02-L116 | 0,35 | Window | 1216Rau0000047157 | 1205Mak2005819720 | St | Fenstermakro, -SmartPart | 2.0002 | 0 | 70 | 70 | 70 | 70 | 0 | 0.9 | - | - | F_Typ3A | Typ 3 | AllplanAttributes (Fenster) - ash D_Plannummer: D1727; Sonnenschutztyp: Movable
Fenster | H2 Ebene +2 | 2.12 | 1.35 | WINDOW | 0 | E02 | 3.0 | Fenster | MainObject | SmartPartCompressed | 100 | 6.1 | 7.5 | FA-1FL-D-1S-E02-L115 | 0,35 | Window | 1216Rau0000047157 | 1205Mak2005819577 | St | Fenstermakro, -SmartPart | 2.0002 | 0 | 70 | 70 | 70 | 70 | 0 | 0.9 | - | - | F_Typ3A | Typ 3 | AllplanAttributes (Fenster) - ash D_Plannummer: D1727; Sonnenschutztyp: Movable
Fenster | H2 Ebene +2 | 2.5 | 1.25 | WINDOW | 0 | E02 | 3.0 | Fenster | MainObject | SmartPartCompressed | 100 | 6.1 | 7.5 | FA-1FL-D-1S-E02-184 | 0,35 | Window | 1216Rau0000046767 | 1205Mak0000281582 | St | Fenstermakro, -SmartPart | 2.1694 | 0 | 70 | 70 | 70 | 70 | 0 | 0.9 | 32 | - | F_Typ3 | Typ 3 | AllplanAttributes (Fenster) - ash D_Plannummer: D1727; Sonnenschutztyp: Movable
Fenster | H2 Ebene +2 | 2.5 | 1.25 | WINDOW | 0 | E02 | 3.0 | Fenster | MainObject | SmartPartCompressed | 100 | 6.1 | 7.5 | FA-1FL-D-1S-E02-183 | 0,35 | Window | 1216Rau0000046781 | 1205Mak0000281567 | St | Fenstermakro, -SmartPart | 2.1694 | 0 | 70 | 70 | 70 | 70 | 0 | 0.9 | 32 | - | F_Typ3 | Typ 3 | AllplanAttributes (Fenster) - ash D_Plannummer: D1727; Sonnenschutztyp: Movable
Fenster | H2 Ebene +2 | 2.12 | 1.35 | WINDOW | 0 | E02 | 3.0 | Fenster | MainObject | SmartPartCompressed | 100 | 6.1 | 7.5 | FA-1FL-D-1S-E02-L129 | 0,35 | Window | 1216Rau0000047485 | 1205Mak0000281533 | St | Fenstermakro, -SmartPart | 2.0002 | 0 | 70 | 70 | 70 | 70 | 0 | 0.9 | 32 | - | F_Typ3A | Typ 3 | AllplanAttributes (Fenster) - ash D_Plannummer: D1727; Sonnenschutztyp: Movable
Fenster | H2 Ebene +2 | 2.12 | 1.35 | WINDOW | 0 | E02 | 3.0 | Fenster | MainObject | SmartPartCompressed | 100 | 6.1 | 7.5 | FA-1FL-D-1S-E02-L127 | 0,35 | Window | 1216Rau0000047633 | 1205Mak0000281472 | St | Fenstermakro, -SmartPart | 2.0002 | 0 | 70 | 70 | 70 | 70 | 0 | 0.9 | 32 | - | F_Typ3A | Typ 3 | AllplanAttributes (Fenster) - ash D_Plannummer: D1727; Sonnenschutztyp: Movable
Fenster | H2 Ebene +2 | 2.12 | 1.35 | WINDOW | 0 | E02 | 3.0 | Fenster | MainObject | SmartPartCompressed | 100 | 6.1 | 7.5 | FA-1FL-D-1S-E02-L123 | 0,35 | Window | 1216Rau0000046083 | 1205Mak2005825997 | St | Fenstermakro, -SmartPart | 1.9932 | 0 | 70 | 70 | 70 | 70 | 0 | 0.9 | 32 | - | F_Typ3A | AllplanAttributes (Fenster) - Sonnenschutztyp: Movable
Fenster | H2 Ebene +2 | 2.12 | 1.35 | WINDOW | 0 | E02 | 3.0 | Fenster | MainObject | SmartPartCompressed | 100 | 6.1 | 7.5 | FA-1FL-D-1S-E02-L124 | 0,35 | Window | 1216Rau0000047457 | 1205Mak0000281652 | St | Fenstermakro, -SmartPart | 2.0002 | 0 | 70 | 70 | 70 | 70 | 0 | 0.9 | 32 | - | F_Typ3A | Typ 3 | AllplanAttributes (Fenster) - ash D_Plannummer: D1727; Sonnenschutztyp: Movable
Fenster | H2 Ebene +2 | 2.12 | 1.35 | WINDOW | 0 | E02 | 3.0 | Fenster | MainObject | SmartPartCompressed | 100 | 6.1 | 7.5 | FA-1FL-D-1S-E02-L128 | 0,35 | Window | 1216Rau0000047471 | 1205Mak0000281500 | St | Fenstermakro, -SmartPart | 2.0002 | 0 | 70 | 70 | 70 | 70 | 0 | 0.9 | 32 | - | F_Typ3A | Typ 3 | AllplanAttributes (Fenster) - ash D_Plannummer: D1727; Sonnenschutztyp: Movable
Fenster | H2 Ebene +2 | 2.5 | 1.25 | WINDOW | 0 | E02 | 3.0 | Fenster | MainObject | SmartPartCompressed | 100 | 6.1 | 7.5 | FA-1FR-D-1S-E02-153 | 0,51 | Window | 1216Rau0000046485 | 1205Mak0000281321 | St | Fenstermakro, -SmartPart | 2.1674 | 0 | 70 | 70 | 70 | 70 | 0 | 0.9 | 32 | - | F_Typ4 | <undefiniert> | AllplanAttributes (Fenster) - Sonnenschutztyp: Movable
Fenster | H2 Ebene +2 | 2.12 | 1.35 | WINDOW | 0 | E02 | 3.0 | Fenster | MainObject | SmartPartCompressed | 100 | 6.1 | 7.5 | FA-1FR-D-1S-E02-L121 | 0,35 | Window | 1216Rau0000046587 | 1205Mak2005824910 | St | Fenstermakro, -SmartPart | 2.0002 | 0 | 70 | 70 | 70 | 70 | 0 | 0.9 | - | - | F_Typ4A | AllplanAttributes (Fenster) - Sonnenschutztyp: Movable
Fenster | H2 Ebene +2 | 2.5 | 2.28 | WINDOW | 0 | E02 | 3.0 | Fenster | MainObject | SmartPartCompressed | 100 | 7.2 | 7.5 | FA-F-E02-197 | 0,49 | Window | 1215Rau0000006926 | 1205Mak0000281345 | St | Fenstermakro, -SmartPart | 4.8852 | 0 | 70 | 70 | 70 | 70 | EI 60 | 2 | - | - | F_Typ39 | <undefiniert> | AllplanAttributes (Fenster) - Sonnenschutztyp: Movable; Gewerk: Zimmer- und Holzbauarbeiten; Selbstschließend: no; ash T_Zulage Schachttür: no; ash T_Dichtschließend: no; ash T_Feststellanlage (FSA): -; ash T_nicht abschließbar: no; Pset_WindowCommon - SmokeStop: yes
Fenster | H2 Ebene +2 | 2.5 | 2.5 | WINDOW | 0 | E02 | 3.0 | Fenster | MainObject | SmartPartCompressed | 100 | 6.1 | 7.5 | FA-1FL-D-1S-X-E02-180 | 0,51 | Window | 1216Rau0000046909 | 1205Mak0000281430 | St | Fenstermakro, -SmartPart | 4.9494 | 0 | 70 | 70 | 70 | 70 | 0 | 0.9 | 35 | - | F_Typ1 | Typ 1 | AllplanAttributes (Fenster) - ash D_Plannummer: D1726; Sonnenschutztyp: Movable
Fenster | H2 Ebene +2 | 2.5 | 2.5 | WINDOW | 0 | E02 | 3.0 | Fenster | MainObject | SmartPartCompressed | 100 | 6.1 | 7.5 | FA-1FR-D-1S-X-E02-179 | 0,51 | Window | 1216Rau0000046947 | 1205Mak0000281632 | St | Fenstermakro, -SmartPart | 4.9494 | 0 | 70 | 70 | 70 | 70 | 0 | 0.9 | 35 | - | F_Typ2 | <undefiniert> | AllplanAttributes (Fenster) - Sonnenschutztyp: Movable
Fenster | H2 Ebene +2 | 2.75 | 2.3945 | WINDOW | 0 |  | 2.2 | Fenster | MainObject | SmartPartCompressed | 100 | 4.1 | 7.5 |  |  |  |  | 1205Mak0000330064 | St | Fenstermakro, -SmartPart | 5.4078 | 0 | 100 | 0 | 0 | 0 |  | 0 |  |  | Codetext | AllplanAttributes (Fenster) - Codetext: Codetext; Gewerk: Metallbau-, Schlosserarbeiten; Funktion: Funktion; Glasart: Glasart; Typ: Typ; Fluchtweg: no; Pset_DoorWindowGlazingType - Shading Coefficient: 0; Pset_WindowCommon - Status: NEW; IsExternal: yes; SmokeStop: no
Fenster | H2 Ebene +2 | 1.12 | 2.3945 | WINDOW | 0 |  | 2.2 | Fenster | MainObject | SmartPartCompressed | 100 | 4.1 | 7.5 |  |  |  |  | 1205Mak0000330005 | St | Fenstermakro, -SmartPart | 2.2745 | 0 | 60 | 60 | 60 | 60 |  | 0 |  |  | Codetext | AllplanAttributes (Fenster) - Codetext: Codetext; Gewerk: Metallbau-, Schlosserarbeiten; Funktion: Funktion; Glasart: Glasart; Typ: Typ; Fluchtweg: no; Pset_DoorWindowGlazingType - Shading Coefficient: 0; Pset_WindowCommon - Status: NEW; IsExternal: yes; SmokeStop: no
Fenster | H2 Ebene +2 | 2.75 | 2.418 | WINDOW | 0 |  | 2.2 | Fenster | MainObject | SmartPartCompressed | 100 | 4.1 | 7.5 |  |  |  |  | 1205Mak0000332067 | St | Fenstermakro, -SmartPart | 5.46678 | 0 | 100 | 0 | 0 | 0 |  | 0 |  |  | Codetext | AllplanAttributes (Fenster) - Codetext: Codetext; Gewerk: Metallbau-, Schlosserarbeiten; Funktion: Funktion; Glasart: Glasart; Typ: Typ; Fluchtweg: no; Pset_DoorWindowGlazingType - Shading Coefficient: 0; Pset_WindowCommon - Status: NEW; IsExternal: yes; SmokeStop: no
Fenster | H2 Ebene +2 | 1.12 | 2.418 | WINDOW | 0 |  | 2.2 | Fenster | MainObject | SmartPartCompressed | 100 | 4.1 | 7.5 |  |  |  |  | 1205Mak0000332089 | St | Fenstermakro, -SmartPart | 2.298 | 0 | 60 | 60 | 60 | 60 |  | 0 |  |  | Codetext | AllplanAttributes (Fenster) - Codetext: Codetext; Gewerk: Metallbau-, Schlosserarbeiten; Funktion: Funktion; Glasart: Glasart; Typ: Typ; Fluchtweg: no; Pset_DoorWindowGlazingType - Shading Coefficient: 0; Pset_WindowCommon - Status: NEW; IsExternal: yes; SmokeStop: no
Fenster | H2 Ebene +2 | 2.5 | 3.92258 | WINDOW | 0 | E01 | 3.0 | Fenster | MainObject | SmartPartCompressed | 100 | 7.2 | 7.5 | FA-1FL-D-2S-E01-123 | 0,35 | Window | 1165Rau0000004749 | 1205Mak0000281468 | St | Fenstermakro, -SmartPart | 8.33749 | 0 | 70 | 70 | 70 | 70 | 0 | 0.9 | 32 | - | F_Typ29 | AllplanAttributes (Fenster) - Sonnenschutztyp: Movable
Fenster | H2 Ebene +2 | 2.5 | 1.65 | WINDOW | 0 | E02 | 3.0 | Fenster | MainObject | SmartPartCompressed | 100 | 6.1 | 7.5 | FA-1FL-D-1S-E02-185 | 0,35 | Window | 1215Rau0000006911 | 1205Mak0000281486 | St | Fenstermakro, -SmartPart | 3.0734 | 0 | 70 | 70 | 70 | 70 | 0 | 0.9 | 32 | - | F_Typ28 | <undefiniert> | AllplanAttributes (Fenster) - Sonnenschutztyp: Movable
Fenster | H2 Ebene +2 | 2.26 | 1.84801 | WINDOW | 0 | E02 | 3.0 | Fenster | MainObject | SmartPartCompressed | 100 | 6.1 | 7.5 | FA-1FL-D-1S-X-E02-189 | 0,35 | Window | 1215Rau0000006920 | 1205Mak0000333729 | St | Fenstermakro, -SmartPart | 3.12597 | 0 | 70 | 70 | 70 | 70 | 0 | 0.9 | - | - | F_Typ9 | <undefiniert> | AllplanAttributes (Fenster) - Sonnenschutztyp: Movable
Fenster | H2 Ebene +2 | 2.26 | 1.8145 | WINDOW | 0 | E02 | 3.0 | Fenster | MainObject | SmartPartCompressed | 100 | 6.1 | 7.5 | FA-1FR-D-1S-X-E02-182 | 0,35 | Window | 1215Rau0000006941 | 1205Mak0000334806 | St | Fenstermakro, -SmartPart | 3.08409 | 0 | 70 | 70 | 70 | 70 | 0 | 0.9 | - | - | F_Typ10 | <undefiniert> | AllplanAttributes (Fenster) - Sonnenschutztyp: Movable
Fenster | H2 Ebene +2 | 2.12 | 1.35 | WINDOW | 0 | E02 | 3.0 | Fenster | MainObject | SmartPartCompressed | 100 | 6.1 | 7.5 | FA-1FL-D-1S-E02-L092c | 0,35 | Window | 1216Rau0000046083 | 1205Mak0000347277 | St | Fenstermakro, -SmartPart | 2.0002 | 0 | 70 | 70 | 70 | 70 | 0 | 0.9 | 32 | - | F_Typ3A | Typ 3 | AllplanAttributes (Fenster) - ash D_Plannummer: D1727; Sonnenschutztyp: Movable
Fenster | H2 Ebene +2 | 2.12 | 1.35 | WINDOW | 0 | E02 | 3.0 | Fenster | MainObject | SmartPartCompressed | 100 | 6.1 | 7.5 | FA-1FL-D-1S-E02-L092b | 0,35 | Window | 1216Rau0000046083 | 1205Mak0000347188 | St | Fenstermakro, -SmartPart | 2.0002 | 0 | 70 | 70 | 70 | 70 | 0 | 0.9 | 32 | - | F_Typ3A | Typ 3 | AllplanAttributes (Fenster) - ash D_Plannummer: D1727; Sonnenschutztyp: Movable
Fenster | H2 Ebene +2 | 2.12 | 1.35 | WINDOW | 0 | E02 | 3.0 | Fenster | MainObject | SmartPartCompressed | 100 | 6.1 | 7.5 | FA-1FL-D-1S-E02-L092a | 0,35 | Window | 1216Rau0000046083 | 1205Mak0000347037 | St | Fenstermakro, -SmartPart | 2.0002 | 0 | 70 | 70 | 70 | 70 | 0 | 0.9 | 32 | - | F_Typ3A | Typ 3 | AllplanAttributes (Fenster) - ash D_Plannummer: D1727; Sonnenschutztyp: Movable
Fenster | H2 Ebene +2 | 2.12 | 1.45 | WINDOW | 0 | E02 | 3.0 | Fenster | MainObject | SmartPartCompressed | 100 | 6.1 | 7.5 | FA-1FL-D-1S-E02-L092d | 0,35 | Window | 1216Rau0000046083 | 1205Mak0000347366 | St | Fenstermakro, -SmartPart | 2.1882 | 0 | 70 | 70 | 70 | 70 | 0 | 0.9 | 32 | - | F_Typ3 | Typ 3 | AllplanAttributes (Fenster) - ash D_Plannummer: D1727; Sonnenschutztyp: Movable
Fenster | H2 Ebene +2 | 2.115 | 1.45 | WINDOW | 0 | E01 | 3.0 | Fenster | MainObject | SmartPartCompressed | 100 | 6.1 | 7.5 | FA-1FL-D-1S-E01-L100a | 0,35 | Window | 1166Rau0000033512 | 1205Mak2005816558 | St | Fenstermakro, -SmartPart | 2.18293 | 0 | 70 | 70 | 70 | 70 | 0 | 0.9 | 32 | - | F_Typ4A | AllplanAttributes (Fenster) - Sonnenschutztyp: Movable
Fenster | H2 Ebene +2 | 2.115 | 1.35 | WINDOW | 0 | E01 | 3.0 | Fenster | MainObject | SmartPartCompressed | 100 | 6.1 | 7.5 | FA-1FL-D-1S-E01-L100b | 0,35 | Window | 1166Rau0000033512 | 1205Mak2005816949 | St | Fenstermakro, -SmartPart | 1.99543 | 0 | 70 | 70 | 70 | 70 | 0 | 0.9 | 32 | - | F_Typ4A | AllplanAttributes (Fenster) - Sonnenschutztyp: Movable
Fenster | H2 Ebene +2 | 2.115 | 1.35 | WINDOW | 0 | E01 | 3.0 | Fenster | MainObject | SmartPartCompressed | 100 | 6.1 | 7.5 | FA-1FL-D-1S-E01-L100c | 0,35 | Window | 1166Rau0000033512 | 1205Mak2005817106 | St | Fenstermakro, -SmartPart | 1.99543 | 0 | 70 | 70 | 70 | 70 | 0 | 0.9 | 32 | - | F_Typ4A | AllplanAttributes (Fenster) - Sonnenschutztyp: Movable
Fenster | H2 Ebene +2 | 2.115 | 1.35 | WINDOW | 0 | E01 | 3.0 | Fenster | MainObject | SmartPartCompressed | 100 | 6.1 | 7.5 | FA-1FL-D-1S-E01-L100d | 0,35 | Window | 1166Rau0000033512 | 1205Mak2005817183 | St | Fenstermakro, -SmartPart | 1.99543 | 0 | 70 | 70 | 70 | 70 | 0 | 0.9 | 32 | - | F_Typ4A | AllplanAttributes (Fenster) - Sonnenschutztyp: Movable
Fenster | H2 Ebene +2 | 2.12 | 1.35 | WINDOW | 0 | E02 | 3.0 | Fenster | MainObject | SmartPartCompressed | 100 | 6.1 | 7.5 | FA-1FL-D-1S-E02-L122d | 0,35 | Window | 1216Rau0000046083 | 1205Mak2005825904 | St | Fenstermakro, -SmartPart | 2.0002 | 0 | 70 | 70 | 70 | 70 | 0 | 0.9 | 32 | - | F_Typ4A | AllplanAttributes (Fenster) - Sonnenschutztyp: Movable
Fenster | H2 Ebene +2 | 2.12 | 1.35 | WINDOW | 0 | E02 | 3.0 | Fenster | MainObject | SmartPartCompressed | 100 | 6.1 | 7.5 | FA-1FL-D-1S-E02-L122c | 0,35 | Window | 1216Rau0000046083 | 1205Mak2005825822 | St | Fenstermakro, -SmartPart | 2.0002 | 0 | 70 | 70 | 70 | 70 | 0 | 0.9 | 32 | - | F_Typ4A | AllplanAttributes (Fenster) - Sonnenschutztyp: Movable
Fenster | H2 Ebene +2 | 2.12 | 1.35 | WINDOW | 0 | E02 | 3.0 | Fenster | MainObject | SmartPartCompressed | 100 | 6.1 | 7.5 | FA-1FL-D-1S-E02-L122b | 0,35 | Window | 1216Rau0000046083 | 1205Mak2005825740 | St | Fenstermakro, -SmartPart | 2.0002 | 0 | 70 | 70 | 70 | 70 | 0 | 0.9 | 32 | - | F_Typ4A | AllplanAttributes (Fenster) - Sonnenschutztyp: Movable
Fenster | H2 Ebene +2 | 2.12 | 1.45 | WINDOW | 0 | E02 | 3.0 | Fenster | MainObject | SmartPartCompressed | 100 | 6.1 | 7.5 | FA-1FL-D-1S-E02-L122a | 0,35 | Window | 1216Rau0000046083 | 1205Mak2005825512 | St | Fenstermakro, -SmartPart | 2.1882 | 0 | 70 | 70 | 70 | 70 | 0 | 0.9 | 32 | - | F_Typ4A | AllplanAttributes (Fenster) - Sonnenschutztyp: Movable
Fenster | H2 Ebene +2 | 2.12 | 1.45 | WINDOW | 0 | E02 | 3.0 | Fenster | MainObject | SmartPartCompressed | 100 | 6.1 | 7.5 | FA-1FL-D-1S-E02-L130d | 0,35 | Window | 1216Rau0000047485 | 1205Mak2005827918 | St | Fenstermakro, -SmartPart | 2.1882 | 0 | 70 | 70 | 70 | 70 | 0 | 0.9 | 32 | - | F_Typ3A | Typ 3 | AllplanAttributes (Fenster) - ash D_Plannummer: D1727; Sonnenschutztyp: Movable
Fenster | H2 Ebene +2 | 2.12 | 1.35 | WINDOW | 0 | E02 | 3.0 | Fenster | MainObject | SmartPartCompressed | 100 | 6.1 | 7.5 | FA-1FL-D-1S-E02-L130a | 0,35 | Window | 1216Rau0000047485 | 1205Mak2005827586 | St | Fenstermakro, -SmartPart | 2.0002 | 0 | 70 | 70 | 70 | 70 | 0 | 0.9 | 32 | - | F_Typ3A | Typ 3 | AllplanAttributes (Fenster) - ash D_Plannummer: D1727; Sonnenschutztyp: Movable
Fenster | H2 Ebene +2 | 2.12 | 1.35 | WINDOW | 0 | E02 | 3.0 | Fenster | MainObject | SmartPartCompressed | 100 | 6.1 | 7.5 | FA-1FL-D-1S-E02-L130b | 0,35 | Window | 1216Rau0000047485 | 1205Mak2005827710 | St | Fenstermakro, -SmartPart | 2.0002 | 0 | 70 | 70 | 70 | 70 | 0 | 0.9 | 32 | - | F_Typ3A | Typ 3 | AllplanAttributes (Fenster) - ash D_Plannummer: D1727; Sonnenschutztyp: Movable
Fenster | H2 Ebene +2 | 2.12 | 1.35 | WINDOW | 0 | E02 | 3.0 | Fenster | MainObject | SmartPartCompressed | 100 | 6.1 | 7.5 | FA-1FL-D-1S-E02-L130c | 0,35 | Window | 1216Rau0000047485 | 1205Mak2005827814 | St | Fenstermakro, -SmartPart | 2.0002 | 0 | 70 | 70 | 70 | 70 | 0 | 0.9 | 32 | - | F_Typ3A | Typ 3 | AllplanAttributes (Fenster) - ash D_Plannummer: D1727; Sonnenschutztyp: Movable
Fenster | H2 Ebene +2 | 2.12 | 1.35 | WINDOW | 0 | E02 | 3.0 | Fenster | MainObject | SmartPartCompressed | 100 | 6.1 | 7.5 | FA-1FL-D-1S-E02-L111a | 0,35 | Window | 1216Rau0000046083 | 1205Mak2005859543 | St | Fenstermakro, -SmartPart | 2.0002 | 0 | 70 | 70 | 70 | 70 | 0 | 0.9 | 32 | - | F_Typ3A | Typ 3 | AllplanAttributes (Fenster) - ash D_Plannummer: D1727; Sonnenschutztyp: Movable
Fenster | H2 Ebene +2 | 2.12 | 1.35 | WINDOW | 0 | E02 | 3.0 | Fenster | MainObject | SmartPartCompressed | 100 | 6.1 | 7.5 | FA-1FL-D-1S-E02-L111 | 0,35 | Window | 1216Rau0000046083 | 1205Mak2005859434 | St | Fenstermakro, -SmartPart | 2.0002 | 0 | 70 | 70 | 70 | 70 | 0 | 0.9 | 32 | - | F_Typ3A | Typ 3 | AllplanAttributes (Fenster) - ash D_Plannummer: D1727; Sonnenschutztyp: Movable
Fenster | H2 Ebene +2 | 2.12 | 1.35 | WINDOW | 0 | E02 | 3.0 | Fenster | MainObject | SmartPartCompressed | 100 | 6.1 | 7.5 | FA-1FL-D-1S-E02-L109 | 0,35 | Window | 1216Rau0000046083 | 1205Mak2005859177 | St | Fenstermakro, -SmartPart | 2.0002 | 0 | 70 | 70 | 70 | 70 | 0 | 0.9 | 32 | - | F_Typ3A | Typ 3 | AllplanAttributes (Fenster) - ash D_Plannummer: D1727; Sonnenschutztyp: Movable
Fenster | H2 Ebene +2 | 2.12 | 1.35 | WINDOW | 0 | E02 | 3.0 | Fenster | MainObject | SmartPartCompressed | 100 | 6.1 | 7.5 | FA-1FL-D-1S-E02-L108 | 0,35 | Window | 1216Rau0000046083 | 1205Mak2005859088 | St | Fenstermakro, -SmartPart | 2.0002 | 0 | 70 | 70 | 70 | 70 | 0 | 0.9 | 32 | - | F_Typ3A | Typ 3 | AllplanAttributes (Fenster) - ash D_Plannummer: D1727; Sonnenschutztyp: Movable
Fenster | H2 Ebene +2 | 2.5 | 2.5 | WINDOW | 0 | E02 | 3.0 | Fenster | MainObject | SmartPartCompressed | 100 | 6.1 | 7.5 | FA-1FR-D-1S-X-E02-195 | 0,51 | Window | 1216Rau0000046237 | 1205Mak0000281353 | St | Fenstermakro, -SmartPart | 4.9494 | 0 | 70 | 70 | 70 | 70 | 0 | 0.9 | 42 | - | F_Typ2 | <undefiniert> | AllplanAttributes (Fenster) - Sonnenschutztyp: Movable
Fenster | H2 Ebene +2 | 2.5 | 2.5 | WINDOW | 0 | E02 | 3.0 | Fenster | MainObject | SmartPartCompressed | 100 | 6.1 | 7.5 | FA-1FL-D-1S-X-E02-196 | 0,51 | Window | 1216Rau0000046211 | 1205Mak0000281349 | St | Fenstermakro, -SmartPart | 4.9494 | 0 | 70 | 70 | 70 | 70 | 0 | 0.9 | 42 | - | F_Typ1 | Typ 1 | AllplanAttributes (Fenster) - ash D_Plannummer: D1726; Sonnenschutztyp: Movable
Fenster | H2 Ebene +2 | 2.5 | 2.5 | WINDOW | 0 | E02 | 3.0 | Fenster | MainObject | SmartPartCompressed | 100 | 6.1 | 7.5 | FA-1FR-D-1S-X-E02-142 | 0,51 | Window | 1216Rau0812778629 | 1205Mak0000281308 | St | Fenstermakro, -SmartPart | 4.9494 | 0 | 70 | 70 | 70 | 70 | 0 | 0.9 | 35 | - | F_Typ2 | <undefiniert> | AllplanAttributes (Fenster) - Sonnenschutztyp: Movable
Fenster | H2 Ebene +2 | 2.5 | 2.5 | WINDOW | 0 | E02 | 3.0 | Fenster | MainObject | SmartPartCompressed | 100 | 6.1 | 7.5 | FA-1FL-D-1S-X-E02-143 | 0,51 | Window | 1216Rau0000045891 | 1205Mak0000281304 | St | Fenstermakro, -SmartPart | 4.9494 | 0 | 70 | 70 | 70 | 70 | 0 | 0.9 | 35 | - | F_Typ1 | Typ 1 | AllplanAttributes (Fenster) - ash D_Plannummer: D1726; Sonnenschutztyp: Movable
Fenster | H2 Ebene +2 | 2.5 | 2.5 | WINDOW | 0 | E02 | 3.0 | Fenster | MainObject | SmartPartCompressed | 100 | 6.1 | 7.5 | FA-1FL-D-1S-X-E02-148 | 0,51 | Window | 1216Rau0000046009 | 1205Mak0000281617 | St | Fenstermakro, -SmartPart | 4.9494 | 0 | 70 | 70 | 70 | 70 | 0 | 0.9 | 35 | - | F_Typ2 | <undefiniert> | AllplanAttributes (Fenster) - Sonnenschutztyp: Movable
Fenster | H2 Ebene +2 | 2.5 | 2.5 | WINDOW | 0 | E02 | 3.0 | Fenster | MainObject | SmartPartCompressed | 100 | 6.1 | 7.5 | FA-1FR-D-1S-X-E02-146 | 0,51 | Window | 1216Rau0000045957 | 1205Mak0000281598 | St | Fenstermakro, -SmartPart | 4.9494 | 0 | 70 | 70 | 70 | 70 | 0 | 0.9 | 35 | - | F_Typ2 | <undefiniert> | AllplanAttributes (Fenster) - Sonnenschutztyp: Movable
Fenster | H2 Ebene +2 | 2.5 | 2.5 | WINDOW | 0 | E02 | 3.0 | Fenster | MainObject | SmartPartCompressed | 100 | 6.1 | 7.5 | FA-1FL-D-1S-X-E02-147 | 0,51 | Window | 1216Rau0000045995 | 1205Mak0000281613 | St | Fenstermakro, -SmartPart | 4.9494 | 0 | 70 | 70 | 70 | 70 | 0 | 0.9 | 35 | - | F_Typ1 | Typ 1 | AllplanAttributes (Fenster) - ash D_Plannummer: D1726; Sonnenschutztyp: Movable
Fenster | H2 Ebene +2 | 2.5 | 2.5 | WINDOW | 0 | E02 | 3.0 | Fenster | MainObject | SmartPartCompressed | 100 | 6.1 | 7.5 | FA-1FL-D-1S-X-E02-144 | 0,51 | Window | 1216Rau0000045905 | 1205Mak0000281644 | St | Fenstermakro, -SmartPart | 4.9494 | 0 | 70 | 70 | 70 | 70 | 0 | 0.9 | 35 | - | F_Typ2 | <undefiniert> | AllplanAttributes (Fenster) - Sonnenschutztyp: Movable
Fenster | H2 Ebene +2 | 2.5 | 2.5 | WINDOW | 0 | E02 | 3.0 | Fenster | MainObject | SmartPartCompressed | 100 | 6.1 | 7.5 | FA-1FL-D-1S-X-E02-145 | 0,51 | Window | 1216Rau0000045943 | 1205Mak0000281571 | St | Fenstermakro, -SmartPart | 4.9494 | 0 | 70 | 70 | 70 | 70 | 0 | 0.9 | 35 | - | F_Typ1 | Typ 1 | AllplanAttributes (Fenster) - ash D_Plannummer: D1726; Sonnenschutztyp: Movable
Fenster | H2 Ebene +2 | 2.5 | 2.5 | WINDOW | 0 | E02 | 3.0 | Fenster | MainObject | SmartPartCompressed | 100 | 6.1 | 7.5 | FA-1FL-D-1S-X-E02-165 | 0,51 | Window | 1216Rau0000047273 | 1205Mak0000281515 | St | Fenstermakro, -SmartPart | 4.9494 | 0 | 70 | 70 | 70 | 70 | 0 | 0.9 | 32 | - | F_Typ1 | Typ 1 | AllplanAttributes (Fenster) - ash D_Plannummer: D1726; Sonnenschutztyp: Movable
Fenster | H2 Ebene +2 | 2.7 | 2.5 | WINDOW | 0 | E02 | 3.0 | Fenster | MainObject | SmartPartCompressed | 100 | 6.1 | 7.5 | FA-1FL-D-1S-X-E02-167 | 0,51 | Window | 1216Rau0000047313 | 1205Mak0000281606 | St | Fenstermakro, -SmartPart | 5.56683 | 0 | 70 | 70 | 70 | 70 | 0 | 0.9 | 32 | - | F_Typ1 | Typ 1 | AllplanAttributes (Fenster) - ash D_Plannummer: D1726; Sonnenschutztyp: Movable
Fenster | H2 Ebene +2 | 2.5 | 2.5 | WINDOW | 0 | E02 | 3.0 | Fenster | MainObject | SmartPartCompressed | 100 | 6.1 | 7.5 | FA-1FR-D-1S-X-E02-166 | 0,51 | Window | 1216Rau0000047287 | 1205Mak0000281636 | St | Fenstermakro, -SmartPart | 4.9494 | 0 | 70 | 70 | 70 | 70 | 0 | 0.9 | 32 | - | F_Typ2 | <undefiniert> | AllplanAttributes (Fenster) - Sonnenschutztyp: Movable
Fenster | H2 Ebene +2 | 2.7 | 2.59901 | WINDOW | 0 | E02 | 3.0 | Fenster | MainObject | SmartPartCompressed | 100 | 7.2 | 7.5 |  |  | Window | 1215Rau0000006896 | 1213Mak0812985881 | St | Fenstermakro, -SmartPart | 5.90239 | 0 | 200 | 80 | 80 | 80 | EI2 60 | AllplanAttributes (Fenster) - Gewerk: Zimmer- und Holzbauarbeiten; Selbstschließend: no; ash T_Zulage Schachttür: no; ash T_Dichtschließend: no; ash T_Feststellanlage (FSA): -; ash T_nicht abschließbar: yes; ash T_Schallschutz: -; Pset_WindowCommon - SmokeStop: no
Fenster | H2 Ebene +2 | 2.7 | 2.569 | WINDOW | 0 | E02 | 3.0 | Fenster | MainObject | SmartPartCompressed | 100 | 7.2 | 7.5 |  |  | Window | 1215Rau0000006896 | 1213Mak0812985884 | St | Fenstermakro, -SmartPart | 5.82978 | 0 | 200 | 80 | 80 | 80 | EI2 60 | AllplanAttributes (Fenster) - Gewerk: Zimmer- und Holzbauarbeiten; Selbstschließend: no; ash T_Zulage Schachttür: no; ash T_Dichtschließend: no; ash T_Feststellanlage (FSA): -; ash T_nicht abschließbar: yes; ash T_Schallschutz: -; Pset_WindowCommon - SmokeStop: no
Fenster | H2 Ebene +2 | 1.88 | 0.64994 | WINDOW | 0 | E02 | 3.0 | Fenster | MainObject | SmartPartCompressed | 100 | 7.2 | 7.5 |  |  | Window | 1216Rau0000046651 | 1213Mak0813201098 | St | Fenstermakro, -SmartPart | 1.22189 | 0 | 0 | 0 | 0 | 0 | EI 30 | AllplanAttributes (Fenster) - Gewerk: Zimmer- und Holzbauarbeiten; Selbstschließend: no; ash T_Zulage Schachttür: no; ash T_Dichtschließend: no; ash T_Feststellanlage (FSA): -; ash T_nicht abschließbar: yes; ash T_Schallschutz: 24 dB; Pset_WindowCommon - SmokeStop: yes
Fenster | H2 Ebene +2 | 1.88 | 0.64994 | WINDOW | 0 | E02 | 3.0 | Fenster | MainObject | SmartPartCompressed | 100 | 7.2 | 7.5 |  |  | Window | 1216Rau0000046651 | 1213Mak0813200409 | St | Fenstermakro, -SmartPart | 1.22189 | 0 | 0 | 0 | 0 | 0 | EI 30 | AllplanAttributes (Fenster) - Gewerk: Zimmer- und Holzbauarbeiten; Selbstschließend: no; ash T_Zulage Schachttür: no; ash T_Dichtschließend: no; ash T_Feststellanlage (FSA): -; ash T_nicht abschließbar: yes; ash T_Schallschutz: 24 dB; Pset_WindowCommon - SmokeStop: yes
TGR 1.5 | H2 Ebene +2 | 1.31 | 1.6 | WINDOW | 0 | E02 | 3.0 | Fenster | MainObject | SmartPartCompressed | 100 | 7.2 | 7.5 | FI-E00-012-001-002 |  | Window | 1116Rau0000066462 | 1213Mak0813507825 | St | Fenstermakro, -SmartPart | 1.7082 | 0 | 70 | 70 | 70 | 70 | EI 30 | AllplanAttributes (Fenster) - Gewerk: Zimmer- und Holzbauarbeiten; Selbstschließend: no; ash T_Zulage Schachttür: no; ash T_Dichtschließend: no; ash T_Feststellanlage (FSA): -; ash T_nicht abschließbar: yes; ash T_Schallschutz: 24 dB; Positionsnummer_Text: S68; Pset_WindowCommon - SmokeStop: yes; AllplanAttributes (TGR 1.5) - Codetext: Typ; V6: 0 m; V7: 0 m; V8: 0 m; V9: 0; Ortscode_Geschoßbezeichnung: E02; Programmversion: 3.1; Objektname: TGR-Makro; Text1: PlanNo.; Bezeichnung: TGR 1.5; Plugin_Bezeichnung: MainObject; Plugin_Objektname: SmartPartCompressed; Gesamtlänge: 10.41; Version: 1.5; OKFF: 7.5; ash T_Türprofilnummer: 7; Positionsnummer_Text: S68; P_ID: 1115Rau0000005189; Allright_Bauteil_ID: 1213Mak0813508004; Abrechnungsart: St
Fenster | H2 Ebene +2 | 1.31 | 1.6 | WINDOW | 0 | E02 | 3.0 | Fenster | MainObject | SmartPartCompressed | 100 | 7.2 | 7.5 |  |  | Window | 1216Rau0000046651 | 1213Mak0813506454 | St | Fenstermakro, -SmartPart | 1.7082 | 0 | 70 | 70 | 70 | 70 | EI 30 | AllplanAttributes (Fenster) - Gewerk: Zimmer- und Holzbauarbeiten; Selbstschließend: no; ash T_Zulage Schachttür: no; ash T_Dichtschließend: no; ash T_Feststellanlage (FSA): -; ash T_nicht abschließbar: yes; ash T_Schallschutz: 24 dB; Pset_WindowCommon - SmokeStop: yes
2 x Fenster | H2 Ebene +2 | 1.23 | 1.05 | WINDOW | 0 | E02 | 3.0 | Fenster | MainObject | SmartPartCompressed | 100 | 7.2 | 7.5 |  |  | Window | 1166Rau0000042125 | 1213Mak0813699678 | St | Fenstermakro, -SmartPart | 0.9919 | 0 | 70 | 70 | 70 | 70 | EI 30 | AllplanAttributes (Fenster) - Gewerk: Zimmer- und Holzbauarbeiten; Selbstschließend: no; ash T_Zulage Schachttür: no; ash T_Dichtschließend: no; ash T_Feststellanlage (FSA): -; ash T_nicht abschließbar: no; ash T_Schallschutz: -; Pset_WindowCommon - SmokeStop: yes
Fenster | H2 Ebene +2 | 1.55 | 1.4725 | WINDOW | 0 | E02 | 3.0 | Fenster | MainObject | SmartPartCompressed | 100 | 7.2 | 7.5 |  |  | Window | 1166Rau0000042125 | 1213Mak0813697860 | St | Fenstermakro, -SmartPart | 1.87882 | 0 | 70 | 70 | 70 | 70 | EI 30 | AllplanAttributes (Fenster) - Gewerk: Zimmer- und Holzbauarbeiten; Selbstschließend: no; ash T_Zulage Schachttür: no; ash T_Dichtschließend: no; ash T_Feststellanlage (FSA): -; ash T_nicht abschließbar: no; ash T_Schallschutz: -; Pset_WindowCommon - SmokeStop: yes
Fenster | H2 Ebene +2 | 1.8 | 4.6076 | WINDOW | 0 | E02 | 3.0 | Fenster | MainObject | SmartPartCompressed | 100 | 7.2 | 7.5 |  |  | Window | 1166Rau0000042125 | 1213Mak0813698229 | St | Fenstermakro, -SmartPart | 7.41622 | 0 | 70 | 70 | 70 | 70 | EI 30 |  |  |  |  | D5 | AllplanAttributes (Fenster) - ash D_Plannummer: 1684; Gewerk: Zimmer- und Holzbauarbeiten; Selbstschließend: no; ash T_Zulage Schachttür: no; ash T_Dichtschließend: no; ash T_Feststellanlage (FSA): -; ash T_nicht abschließbar: no; ash T_Schallschutz: -; Pset_WindowCommon - SmokeStop: yes
Fenster | H2 Ebene +2 | 1.55 | 1.4619 | WINDOW | 0 | E02 | 3.0 | Fenster | MainObject | SmartPartCompressed | 100 | 7.2 | 7.5 |  |  | Window | 1166Rau0000042125 | 1213Mak0813698322 | St | Fenstermakro, -SmartPart | 1.86388 | 0 | 70 | 70 | 70 | 70 | EI 30 | AllplanAttributes (Fenster) - Gewerk: Zimmer- und Holzbauarbeiten; Selbstschließend: no; ash T_Zulage Schachttür: no; ash T_Dichtschließend: no; ash T_Feststellanlage (FSA): -; ash T_nicht abschließbar: no; ash T_Schallschutz: -; Pset_WindowCommon - SmokeStop: yes
Fenster | H2 Ebene +2 | 1.23 | 1.05 | WINDOW | 0 | E02 | 3.0 | Fenster | MainObject | SmartPartCompressed | 100 | 7.2 | 7.5 |  |  | Window | 1166Rau0000042125 | 1213Mak0813698923 | St | Fenstermakro, -SmartPart | 0.9919 | 0 | 70 | 70 | 70 | 70 | EI 30 | AllplanAttributes (Fenster) - Gewerk: Zimmer- und Holzbauarbeiten; Selbstschließend: no; ash T_Zulage Schachttür: no; ash T_Dichtschließend: no; ash T_Feststellanlage (FSA): -; ash T_nicht abschließbar: no; ash T_Schallschutz: -; Pset_WindowCommon - SmokeStop: yes
Fenster | H2 Ebene +2 | 1.55 | 2.185 | WINDOW | 0 | E02 | 3.0 | Fenster | MainObject | SmartPartCompressed | 100 | 7.2 | 7.5 |  |  | Window | 1166Rau0000042125 | 1213Mak0813698643 | St | Fenstermakro, -SmartPart | 2.88345 | 0 | 70 | 70 | 70 | 70 | EI 30 |  |  |  |  | D6 | AllplanAttributes (Fenster) - ash D_Plannummer: 1684; Gewerk: Zimmer- und Holzbauarbeiten; Selbstschließend: no; ash T_Zulage Schachttür: no; ash T_Dichtschließend: no; ash T_Feststellanlage (FSA): -; ash T_nicht abschließbar: no; ash T_Schallschutz: -; Pset_WindowCommon - SmokeStop: yes
Fenster | H2 Ebene +2 | 1.23 | 1.923 | WINDOW | 0 | E02 | 3.0 | Fenster | MainObject | SmartPartCompressed | 100 | 7.2 | 7.5 |  |  | Window | 1166Rau0000042125 | 1213Mak0813698672 | St | Fenstermakro, -SmartPart | 1.94347 | 0 | 70 | 70 | 70 | 70 | EI 30 | AllplanAttributes (Fenster) - Gewerk: Zimmer- und Holzbauarbeiten; Selbstschließend: no; ash T_Zulage Schachttür: no; ash T_Dichtschließend: no; ash T_Feststellanlage (FSA): -; ash T_nicht abschließbar: no; ash T_Schallschutz: -; Pset_WindowCommon - SmokeStop: yes
2 x Fenster | H2 Ebene +2 | 1.23 | 3.095 | WINDOW | 0 | E02 | 3.0 | Fenster | MainObject | SmartPartCompressed | 100 | 7.2 | 7.5 |  |  | Window | 1166Rau0000042125 | 1213Mak0813699738 | St | Fenstermakro, -SmartPart | 3.10275 | 0 | 70 | 70 | 70 | 70 | EI 30 | AllplanAttributes (Fenster) - Gewerk: Zimmer- und Holzbauarbeiten; Selbstschließend: no; ash T_Zulage Schachttür: no; ash T_Dichtschließend: no; ash T_Feststellanlage (FSA): -; ash T_nicht abschließbar: no; ash T_Schallschutz: -; Pset_WindowCommon - SmokeStop: yes
Fenster | H2 Ebene +2 | 1.51 | 2.22 | WINDOW | 0 | E02 | 3.0 | Fenster | MainObject | SmartPartCompressed | 100 | 7.2 | 7.5 |  |  | Window | 1166Rau0000042125 | 1213Mak0813699769 | St | Fenstermakro, -SmartPart | 2.8496 | 0 | 70 | 70 | 70 | 70 | EI 30 |  |  |  |  | D6 | AllplanAttributes (Fenster) - ash D_Plannummer: 1684; Gewerk: Zimmer- und Holzbauarbeiten; Selbstschließend: no; ash T_Zulage Schachttür: no; ash T_Dichtschließend: no; ash T_Feststellanlage (FSA): -; ash T_nicht abschließbar: no; ash T_Schallschutz: -; Pset_WindowCommon - SmokeStop: yes
Symbol BD | H2 Ebene +2 | 1.102 | 0.442 | SKYLIGHT | AllplanAttributes (Symbol BD) - V6: 0 m; V7: 0 m; V8: 0 m; V9: 0; Programmversion: 3.0; Objektname: Bodendurchbruchsmakro; Bezeichnung: Symbol BD; Plugin_Bezeichnung: MainObject; Plugin_Objektname: SmartPartCompressed; Version: 1.0; Attributset-Objekt: Opening; Allright_Bauteil_ID: 1214Mak0813473010; Abrechnungsart: St
Symbol BD | H2 Ebene +2 | 1.102 | 0.442 | SKYLIGHT | AllplanAttributes (Symbol BD) - V6: 0 m; V7: 0 m; V8: 0 m; V9: 0; Programmversion: 3.0; Objektname: Bodendurchbruchsmakro; Bezeichnung: Symbol BD; Plugin_Bezeichnung: MainObject; Plugin_Objektname: SmartPartCompressed; Version: 1.0; Attributset-Objekt: Opening; Allright_Bauteil_ID: 1214Mak0813475183; Abrechnungsart: St
Symbol BD | H2 Ebene +2 | 1.102 | 0.442 | SKYLIGHT | AllplanAttributes (Symbol BD) - V6: 0 m; V7: 0 m; V8: 0 m; V9: 0; Programmversion: 3.0; Objektname: Bodendurchbruchsmakro; Bezeichnung: Symbol BD; Plugin_Bezeichnung: MainObject; Plugin_Objektname: SmartPartCompressed; Version: 1.0; Attributset-Objekt: Opening; Allright_Bauteil_ID: 1214Mak0813473072; Abrechnungsart: St
Symbol BD | H2 Ebene +2 | 3 | 1.1275 | SKYLIGHT |  |  |  |  |  |  |  |  |  |  |  |  |  |  |  |  |  |  |  |  |  |  | 0 | 0.9 | 32 | - | AllplanAttributes (Symbol BD) - V6: 0 m; V7: 0 m; V8: 0 m; V9: 0; Programmversion: 3.0; Objektname: Bodendurchbruchsmakro; Bezeichnung: Symbol BD; Plugin_Bezeichnung: MainObject; Plugin_Objektname: SmartPartCompressed; Version: 1.0; Sonnenschutztyp: Movable; g-Wert: 0,51; Attributset-Objekt: Opening; Allright_Bauteil_ID: 1214Mak0813471154; Abrechnungsart: St
Symbol BD | H2 Ebene +2 | 3 | 1.1275 | SKYLIGHT |  |  |  |  |  |  |  |  |  |  |  |  |  |  |  |  |  |  |  |  |  |  | 0 | 0.9 | 32 | - | AllplanAttributes (Symbol BD) - V6: 0 m; V7: 0 m; V8: 0 m; V9: 0; Programmversion: 3.0; Objektname: Bodendurchbruchsmakro; Bezeichnung: Symbol BD; Plugin_Bezeichnung: MainObject; Plugin_Objektname: SmartPartCompressed; Version: 1.0; Sonnenschutztyp: Movable; g-Wert: 0,51; Attributset-Objekt: Opening; Allright_Bauteil_ID: 1214Mak0813471119; Abrechnungsart: St
Symbol BD | H2 Ebene +2 | 1.55005 | 0.511 | SKYLIGHT |  |  |  |  |  |  |  |  |  |  |  |  |  |  |  |  |  |  |  |  |  |  | 0 | 0.9 | 32 | - | AllplanAttributes (Symbol BD) - V6: 0 m; V7: 0 m; V8: 0 m; V9: 0; Programmversion: 3.0; Objektname: Bodendurchbruchsmakro; Bezeichnung: Symbol BD; Plugin_Bezeichnung: MainObject; Plugin_Objektname: SmartPartCompressed; Version: 1.0; Sonnenschutztyp: Movable; g-Wert: 0,51; Attributset-Objekt: Opening; Allright_Bauteil_ID: 1214Mak0813475088; Abrechnungsart: St
Symbol BD | H2 Ebene +2 | 1.463 | 0.69792 | SKYLIGHT |  |  |  |  |  |  |  |  |  |  |  |  |  |  |  |  |  |  |  |  |  |  | 0 | 0.9 | 32 | - | AllplanAttributes (Symbol BD) - V6: 0 m; V7: 0 m; V8: 0 m; V9: 0; Programmversion: 3.0; Objektname: Bodendurchbruchsmakro; Bezeichnung: Symbol BD; Plugin_Bezeichnung: MainObject; Plugin_Objektname: SmartPartCompressed; Version: 1.0; Sonnenschutztyp: Movable; g-Wert: 0,51; Attributset-Objekt: Opening; Allright_Bauteil_ID: 1214Mak0813475102; Abrechnungsart: St
Symbol BD | H2 Ebene +2 | 3.03 | 2.45 | SKYLIGHT |  |  |  |  |  |  |  |  |  |  |  |  |  |  |  |  |  |  |  |  |  |  | 0 | 0.9 | 32 | - | AllplanAttributes (Symbol BD) - V6: 0 m; V7: 0 m; V8: 0 m; V9: 0; Programmversion: 3.0; Objektname: Bodendurchbruchsmakro; Bezeichnung: Symbol BD; Plugin_Bezeichnung: MainObject; Plugin_Objektname: SmartPartCompressed; Version: 1.0; Sonnenschutztyp: Movable; g-Wert: 0,51; Attributset-Objekt: Opening; Allright_Bauteil_ID: 1214Mak0813471048; Abrechnungsart: St
Symbol BD | H2 Ebene +2 | 3.03 | 2.45 | SKYLIGHT |  |  |  |  |  |  |  |  |  |  |  |  |  |  |  |  |  |  |  |  |  |  | 0 | 0.9 | 32 | - | AllplanAttributes (Symbol BD) - V6: 0 m; V7: 0 m; V8: 0 m; V9: 0; Programmversion: 3.0; Objektname: Bodendurchbruchsmakro; Bezeichnung: Symbol BD; Plugin_Bezeichnung: MainObject; Plugin_Objektname: SmartPartCompressed; Version: 1.0; Sonnenschutztyp: Movable; g-Wert: 0,51; Attributset-Objekt: Opening; Allright_Bauteil_ID: 1214Mak0813471086; Abrechnungsart: St
Fenster | H2 Ebene +1 | 2.115 | 1.35 | WINDOW | 0 | E01 | 3.0 | Fenster | MainObject | SmartPartCompressed | 100 | 6.1 | 3.75 | FA-1FR-D-1S-E01-L048 | 0,35 | Window | 1166Rau0000033512 | 1155Mak0000003502 | St | Fenstermakro, -SmartPart | 1.99543 | 0 | 70 | 70 | 70 | 70 | 0 | 0.9 | 32 | - | F_Typ4A | AllplanAttributes (Fenster) - Sonnenschutztyp: Movable
Fenster | H2 Ebene +1 | 2.115 | 1.35 | WINDOW | 0 | E01 | 3.0 | Fenster | MainObject | SmartPartCompressed | 100 | 6.1 | 3.75 | FA-1FR-D-1S-E01-L050 | 0,35 | Window | 1166Rau0000033512 | 1155Mak0000003512 | St | Fenstermakro, -SmartPart | 1.99543 | 0 | 70 | 70 | 70 | 70 | 0 | 0.9 | 32 | - | F_Typ4A | AllplanAttributes (Fenster) - Sonnenschutztyp: Movable
Fenster | H2 Ebene +1 | 2.115 | 0.725 | WINDOW | 0 | E01 | 3.0 | Fenster | MainObject | SmartPartCompressed | 100 | 6.1 | 3.75 | FA-F-E01-L051 | 0,35 | Window | 1166Rau0000033157 | 1155Mak0000003506 | St | Fenstermakro, -SmartPart | 1.11442 | 0 | 70 | 70 | 70 | 70 | 0 | 0.9 | 32 | - | F_Typ6 | AllplanAttributes (Fenster) - Sonnenschutztyp: Movable
Fenster | H2 Ebene +1 | 2.115 | 1.35 | WINDOW | 0 | E01 | 3.0 | Fenster | MainObject | SmartPartCompressed | 100 | 6.1 | 3.75 | FA-1FR-D-1S-E01-L053 | 0,35 | Window | 1166Rau0000033512 | 1155Mak0000003518 | St | Fenstermakro, -SmartPart | 1.99543 | 0 | 70 | 70 | 70 | 70 | 0 | 0.9 | 32 | - | F_Typ4A | AllplanAttributes (Fenster) - Sonnenschutztyp: Movable
Fenster | H2 Ebene +1 | 2.115 | 0.725 | WINDOW | 0 | E01 | 3.0 | Fenster | MainObject | SmartPartCompressed | 100 | 6.1 | 3.75 | FA-F-E01-L054 | 0,35 | Window | 1166Rau0000033131 | 1155Mak0000003521 | St | Fenstermakro, -SmartPart | 1.11442 | 0 | 70 | 70 | 70 | 70 | 0 | 0.9 | 32 | - | F_Typ6 | AllplanAttributes (Fenster) - Sonnenschutztyp: Movable
Fenster | H2 Ebene +1 | 2.115 | 1.35 | WINDOW | 0 | E01 | 3.0 | Fenster | MainObject | SmartPartCompressed | 100 | 6.1 | 3.75 | FA-1FR-D-1S-E01-L052 | 0,35 | Window | 1166Rau0000033512 | 1155Mak0000003515 | St | Fenstermakro, -SmartPart | 1.99543 | 0 | 70 | 70 | 70 | 70 | 0 | 0.9 | 32 | - | F_Typ4A | AllplanAttributes (Fenster) - Sonnenschutztyp: Movable
Fenster | H2 Ebene +1 | 2.5 | 2.5 | WINDOW | 0 | E01 | 3.0 | Fenster | MainObject | SmartPartCompressed | 100 | 6.1 | 3.75 | FA-1FL-D-1S-X-E01-114 | 0,51 | Window | 1166Rau0000034427 | 1155Mak0000012308 | St | Fenstermakro, -SmartPart | 4.9494 | 0 | 70 | 70 | 70 | 70 | 0 | 0.9 | 35 | - | F_Typ1 | Typ1 | AllplanAttributes (Fenster) - ash D_Plannummer: D1726; Sonnenschutztyp: Movable
Fenster | H2 Ebene +1 | 2.5 | 2.5 | WINDOW | 0 | E01 | 3.0 | Fenster | MainObject | SmartPartCompressed | 100 | 6.1 | 3.75 | FA-1FR-D-1S-X-E01-115 | 0,51 | Window | 1166Rau0000034440 | 1155Mak0000012296 | St | Fenstermakro, -SmartPart | 4.9494 | 0 | 70 | 70 | 70 | 70 | 0 | 0.9 | 35 | - | F_Typ2 | AllplanAttributes (Fenster) - Sonnenschutztyp: Movable
Fenster | H2 Ebene +1 | 2.5 | 2.5 | WINDOW | 0 | E01 | 3.0 | Fenster | MainObject | SmartPartCompressed | 100 | 6.1 | 3.75 | FA-1FL-D-1S-X-E01-112 | 0,51 | Window | 1166Rau0000034401 | 1155Mak0000012314 | St | Fenstermakro, -SmartPart | 4.9494 | 0 | 70 | 70 | 70 | 70 | 0 | 0.9 | 35 | - | F_Typ1 | Typ1 | AllplanAttributes (Fenster) - ash D_Plannummer: D1726; Sonnenschutztyp: Movable
Fenster | H2 Ebene +1 | 2.5 | 2.5 | WINDOW | 0 | E01 | 3.0 | Fenster | MainObject | SmartPartCompressed | 100 | 6.1 | 3.75 | FA-1FR-D-1S-X-E01-113 | 0,51 | Window | 1166Rau0000034414 | 1155Mak0000012311 | St | Fenstermakro, -SmartPart | 4.9494 | 0 | 70 | 70 | 70 | 70 | 0 | 0.9 | 35 | - | F_Typ2 | AllplanAttributes (Fenster) - Sonnenschutztyp: Movable
Fenster | H2 Ebene +1 | 2.5 | 2.5 | WINDOW | 0 | E01 | 3.0 | Fenster | MainObject | SmartPartCompressed | 100 | 6.1 | 3.75 | FA-1FR-D-1S-X-E01-129 | 0,51 | Window | 1166Rau0000033320 | 1155Mak0000012281 | St | Fenstermakro, -SmartPart | 4.9494 | 0 | 70 | 70 | 70 | 70 | 0 | 0.9 | 39 | - | F_Typ2 | AllplanAttributes (Fenster) - Sonnenschutztyp: Movable
Fenster | H2 Ebene +1 | 2.5 | 2.5 | WINDOW | 0 | E01 | 3.0 | Fenster | MainObject | SmartPartCompressed | 100 | 6.1 | 3.75 | FA-1FL-DK-1S-X-E01-128 | 0,51 | Window | 1166Rau0000033307 | 1155Mak0000012278 | St | Fenstermakro, -SmartPart | 4.9494 | 0 | 70 | 70 | 70 | 70 | 0 | 0.9 | 39 | - | F_Typ1 | Typ1 | AllplanAttributes (Fenster) - ash D_Plannummer: D1726; Sonnenschutztyp: Movable
Fenster | H2 Ebene +1 | 2.5 | 2.5 | WINDOW | 0 | E01 | 3.0 | Fenster | MainObject | SmartPartCompressed | 100 | 6.1 | 3.75 | FA-1FR-D-1S-X-E01-131 | 0,51 | Window | 1166Rau0000033346 | 1155Mak0000012287 | St | Fenstermakro, -SmartPart | 4.9494 | 0 | 70 | 70 | 70 | 70 | 0 | 0.9 | 42 | - | F_Typ2 | AllplanAttributes (Fenster) - Sonnenschutztyp: Movable
Fenster | H2 Ebene +1 | 2.5 | 2.5 | WINDOW | 0 | E01 | 3.0 | Fenster | MainObject | SmartPartCompressed | 100 | 6.1 | 3.75 | FA-1FL-D-1S-X-E01-130 | 0,51 | Window | 1166Rau0000033333 | 1155Mak0000012284 | St | Fenstermakro, -SmartPart | 4.9494 | 0 | 70 | 70 | 70 | 70 | 0 | 0.9 | 42 | - | F_Typ1 | Typ1 | AllplanAttributes (Fenster) - ash D_Plannummer: D1726; Sonnenschutztyp: Movable
Fenster | H2 Ebene +1 | 2.5 | 2.5 | WINDOW | 0 | E01 | 3.0 | Fenster | MainObject | SmartPartCompressed | 100 | 6.1 | 3.75 | FA-1FL-DK-1S-X-E01-081 | 0,51 | Window | 1166Rau0000033573 | 1155Mak0000012350 | St | Fenstermakro, -SmartPart | 4.9494 | 0 | 70 | 70 | 70 | 70 | 0 | 0.9 | 35 | - | F_Typ1 | Typ1 | AllplanAttributes (Fenster) - ash D_Plannummer: D1726; Sonnenschutztyp: Movable
Fenster | H2 Ebene +1 | 2.5 | 2.5 | WINDOW | 0 | E01 | 3.0 | Fenster | MainObject | SmartPartCompressed | 100 | 6.1 | 3.75 | FA-1FR-D-1S-X-E01-082 | 0,51 | Window | 1166Rau0000033586 | 1155Mak0000012347 | St | Fenstermakro, -SmartPart | 4.9494 | 0 | 70 | 70 | 70 | 70 | 0 | 0.9 | 35 | - | F_Typ2 | AllplanAttributes (Fenster) - Sonnenschutztyp: Movable
Fenster | H2 Ebene +1 | 2.5 | 2.5 | WINDOW | 0 | E01 | 3.0 | Fenster | MainObject | SmartPartCompressed | 100 | 6.1 | 3.75 | FA-1FL-DK-1S-X-E01-083 | 0,51 | Window | 1166Rau0000033599 | 1155Mak0000012344 | St | Fenstermakro, -SmartPart | 4.9494 | 0 | 70 | 70 | 70 | 70 | 0 | 0.9 | 35 | - | F_Typ1 | Typ1 | AllplanAttributes (Fenster) - ash D_Plannummer: D1726; Sonnenschutztyp: Movable
Fenster | H2 Ebene +1 | 2.5 | 2.5 | WINDOW | 0 | E01 | 3.0 | Fenster | MainObject | SmartPartCompressed | 100 | 6.1 | 3.75 | FA-1FR-DK-1S-X-E01-084 | 0,51 | Window | 1166Rau0000033612 | 1155Mak0000012341 | St | Fenstermakro, -SmartPart | 4.9494 | 0 | 70 | 70 | 70 | 70 | 0 | 0.9 | 35 | - | F_Typ2 | AllplanAttributes (Fenster) - Sonnenschutztyp: Movable
Fenster | H2 Ebene +1 | 2.5 | 2.5 | WINDOW | 0 | E01 | 3.0 | Fenster | MainObject | SmartPartCompressed | 100 | 6.1 | 3.75 | FA-1FL-D-1S-X-E01-085 | 0,51 | Window | 1166Rau0000033625 | 1155Mak0000012338 | St | Fenstermakro, -SmartPart | 4.9494 | 0 | 70 | 70 | 70 | 70 | 0 | 0.9 | 35 | - | F_Typ1 | Typ1 | AllplanAttributes (Fenster) - ash D_Plannummer: D1726; Sonnenschutztyp: Movable
Fenster | H2 Ebene +1 | 2.5 | 2.28 | WINDOW | 0 | E00 | 3.0 | Fenster | MainObject | SmartPartCompressed | 100 | 6.1 | 3.75 | FA-1FL-D-1S-X-E01-109 | 0,35 | Window | 1165Rau0000004712 | 1155Mak0000002863 | St | Fenstermakro, -SmartPart | 4.4972 | 0 | 70 | 70 | 70 | 70 | 0 | 0.9 | 32 | RC 1 | F_Typ38 | AllplanAttributes (Fenster) - Gewerk: Fensterarbeiten; Pset_WindowCommon - Status: NEW; IsExternal: yes
Fenster | H2 Ebene +1 | 2.5 | 2.28 | WINDOW | 0 | E00 | 3.0 | Fenster | MainObject | SmartPartCompressed | 100 | 6.1 | 3.75 | FA-1FR-D-1S-X-E01-111 | 0,35 | Window | 1165Rau0000004736 | 1155Mak0000003011 | St | Fenstermakro, -SmartPart | 4.4972 | 0 | 70 | 70 | 70 | 70 | 0 | 0.9 | 32 | RC 1 | F_Typ7 | AllplanAttributes (Fenster) - Gewerk: Fensterarbeiten; Pset_WindowCommon - Status: NEW; IsExternal: yes
Fenster | H2 Ebene +1 | 2.115 | 1.35 | WINDOW | 0 | E01 | 3.0 | Fenster | MainObject | SmartPartCompressed | 100 | 6.1 | 3.75 | FA-1FL-D-1S-E01-L061 | 0,35 | Window | 1166Rau0000033512 | 1155Mak0000003494 | St | Fenstermakro, -SmartPart | 1.99543 | 0 | 70 | 70 | 70 | 70 | 0 | 0.9 | 32 | - | F_Typ3A | Typ3 | AllplanAttributes (Fenster) - ash D_Plannummer: D1727; Sonnenschutztyp: Movable
Fenster | H2 Ebene +1 | 2.115 | 1.35 | WINDOW | 0 | E01 | 3.0 | Fenster | MainObject | SmartPartCompressed | 100 | 6.1 | 3.75 | FA-1FL-D-1S-E01-L058 | 0,35 | Window | 1166Rau0000033512 | 1155Mak0000003484 | St | Fenstermakro, -SmartPart | 1.99543 | 0 | 70 | 70 | 70 | 70 | 0 | 0.9 | 32 | - | F_Typ3A | Typ3 | AllplanAttributes (Fenster) - ash D_Plannummer: D1727; Sonnenschutztyp: Movable
Fenster | H2 Ebene +1 | 2.115 | 1.35 | WINDOW | 0 | E01 | 3.0 | Fenster | MainObject | SmartPartCompressed | 100 | 6.1 | 3.75 | FA-1FL-D-1S-E01-L062 | 0,35 | Window | 1166Rau0000033512 | 1155Mak2005719868 | St | Fenstermakro, -SmartPart | 1.99543 | 0 | 70 | 70 | 70 | 70 | 0 | 0.9 | 32 | - | F_Typ3A | Typ3 | AllplanAttributes (Fenster) - ash D_Plannummer: D1727; Sonnenschutztyp: Movable
Fenster | H2 Ebene +1 | 2.115 | 1.35 | WINDOW | 0 | E01 | 3.0 | Fenster | MainObject | SmartPartCompressed | 100 | 6.1 | 3.75 | FA-1FL-D-1S-E01-L056 | 0,35 | Window | 1166Rau0000033512 | 1155Mak0000003478 | St | Fenstermakro, -SmartPart | 1.99543 | 0 | 70 | 70 | 70 | 70 | 0 | 0.9 | 32 | - | F_Typ3A | Typ3 | AllplanAttributes (Fenster) - ash D_Plannummer: D1727; Sonnenschutztyp: Movable
Fenster | H2 Ebene +1 | 2.115 | 1.35 | WINDOW | 0 | E01 | 3.0 | Fenster | MainObject | SmartPartCompressed | 100 | 6.1 | 3.75 | FA-1FL-D-1S-E01-L057 | 0,35 | Window | 1166Rau0000033512 | 1155Mak0000003481 | St | Fenstermakro, -SmartPart | 1.99543 | 0 | 70 | 70 | 70 | 70 | 0 | 0.9 | 32 | - | F_Typ3A | Typ3 | AllplanAttributes (Fenster) - ash D_Plannummer: D1727; Sonnenschutztyp: Movable
Fenster | H2 Ebene +1 | 2.115 | 1.35 | WINDOW | 0 | E01 | 3.0 | Fenster | MainObject | SmartPartCompressed | 100 | 6.1 | 3.75 | FA-1FR-D-1S-E01-L075 | 0,35 | Window | 1166Rau0000033512 | 1155Mak2005783748 | St | Fenstermakro, -SmartPart | 1.99543 | 0 | 70 | 70 | 70 | 70 | 0 | 0.9 | 32 | - | F_Typ4A | AllplanAttributes (Fenster) - Sonnenschutztyp: Movable
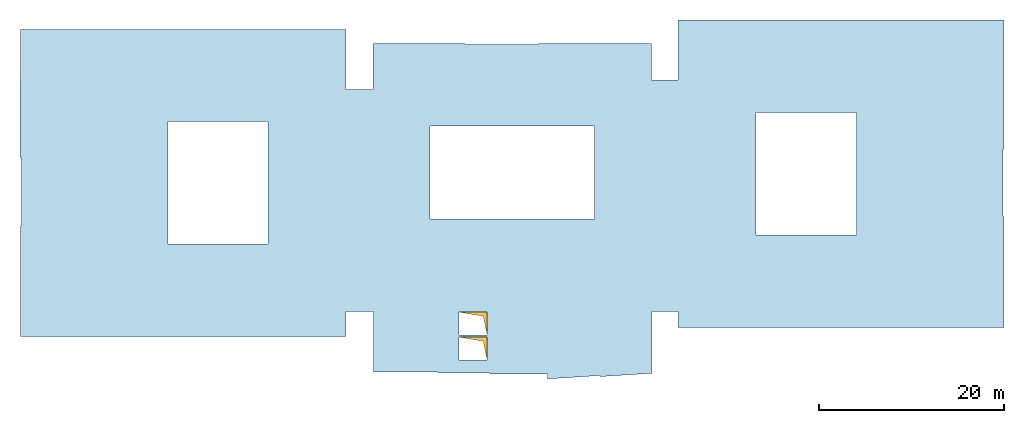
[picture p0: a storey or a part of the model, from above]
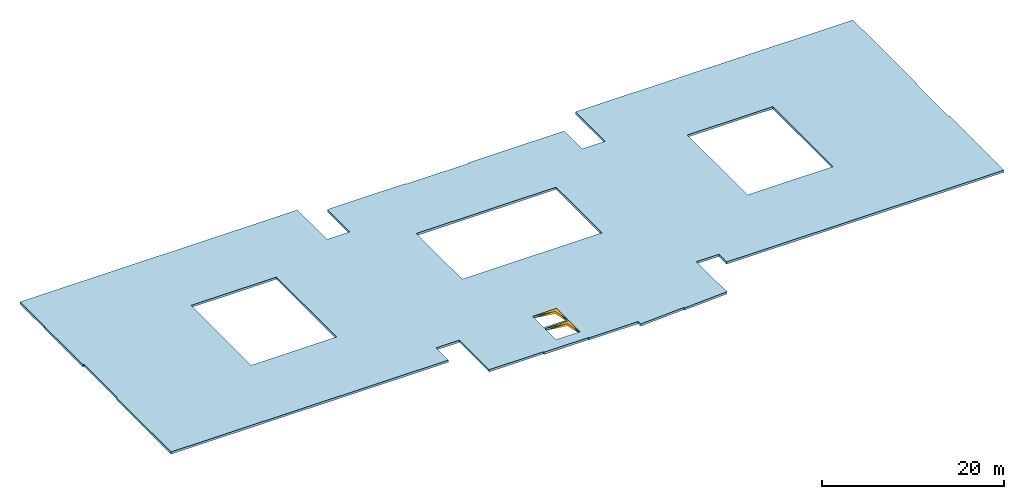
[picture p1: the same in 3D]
Properties of the parts of a building model (IFC4), part 79 of 80

# IfcWindow (393)
Name | In | OverallHeight (m) | OverallWidth (m) | PredefinedType | AllplanAttributes (Fenster), V6 (m) = AllplanAttributes (Fenster), V7 (m) = AllplanAttributes (Fenster), V8 (m) = AllplanAttributes (Fenster), V9 = HeightWindowSillOutside = HeightWindowSillInside | AllplanAttributes (Fenster), Ortscode_Geschoßbezeichnung | AllplanAttributes (Fenster), Programmversion | AllplanAttributes (Fenster), Bezeichnung | AllplanAttributes (Fenster), Plugin_Bezeichnung | AllplanAttributes (Fenster), Plugin_Objektname | AllplanAttributes (Fenster), Glasanteil_berücksichtigen | AllplanAttributes (Fenster), Version | AllplanAttributes (Fenster), OKFF | ash T_Tür-Nr. | AllplanAttributes (Fenster), g-Wert | AllplanAttributes (Fenster), Attributset-Objekt | AllplanAttributes (Fenster), P_ID | AllplanAttributes (Fenster), Allright_Bauteil_ID | AllplanAttributes (Fenster), Abrechnungsart | AllplanAttributes (Fenster), Objektname | GlassSurface | OffsetOpeningBottom = OffsetOpeningTop = OffsetOpeningLeft = OffsetOpeningRight | DeductionOpeningBottom | DeductionOpeningLeft | DeductionOpeningRight | DeductionOpeningTop | FireRating | ThermalTransmittance (W/K/m2) | AcousticRating | SecurityRating | Reference | AllplanAttributes (Fenster), ash D_Detailverweis
Fenster | H2 Ebene +1 | 2.115 | 1.35 | WINDOW | 0 | E01 | 3.0 | Fenster | MainObject | SmartPartCompressed | 100 | 6.1 | 3.75 | FA-1FL-D-1S-E01-L069 | 0,35 | Window | 1166Rau0000033512 | 1155Mak2005796589 | St | Fenstermakro, -SmartPart | 1.99543 | 0 | 70 | 70 | 70 | 70 | 0 | 0.9 | 32 | - | F_Typ3A | Typ3 | AllplanAttributes (Fenster) - ash D_Plannummer: D1727; Sonnenschutztyp: Movable
Fenster | H2 Ebene +1 | 2.115 | 1.35 | WINDOW | 0 | E01 | 3.0 | Fenster | MainObject | SmartPartCompressed | 100 | 6.1 | 3.75 | FA-1FL-D-1S-E01-L067 | 0,35 | Window | 1166Rau0000033512 | 1155Mak2005796819 | St | Fenstermakro, -SmartPart | 1.99543 | 0 | 70 | 70 | 70 | 70 | 0 | 0.9 | 32 | - | F_Typ3A | Typ3 | AllplanAttributes (Fenster) - ash D_Plannummer: D1727; Sonnenschutztyp: Movable
Fenster | H2 Ebene +1 | 2.115 | 1.35 | WINDOW | 0 | E01 | 3.0 | Fenster | MainObject | SmartPartCompressed | 100 | 6.1 | 3.75 | FA-1FL-D-1S-E01-L071 | 0,35 | Window | 1166Rau0000033512 | 1155Mak2005786201 | St | Fenstermakro, -SmartPart | 1.99543 | 0 | 70 | 70 | 70 | 70 | 0 | 0.9 | 32 | - | F_Typ3A | Typ3 | AllplanAttributes (Fenster) - ash D_Plannummer: D1727; Sonnenschutztyp: Movable
Fenster | H2 Ebene +1 | 2.115 | 1.35 | WINDOW | 0 | E01 | 3.0 | Fenster | MainObject | SmartPartCompressed | 100 | 6.1 | 3.75 | FA-1FL-D-1S-E01-L070 | 0,35 | Window | 1166Rau0000033512 | 1155Mak2005786117 | St | Fenstermakro, -SmartPart | 1.99543 | 0 | 70 | 70 | 70 | 70 | 0 | 0.9 | 32 | - | F_Typ3A | Typ3 | AllplanAttributes (Fenster) - ash D_Plannummer: D1727; Sonnenschutztyp: Movable
Fenster | H2 Ebene +1 | 2.115 | 2.6 | WINDOW | 0 | E01 | 3.0 | Fenster | MainObject | SmartPartCompressed | 100 | 6.1 | 3.75 | FA-2FLR-D-1S-E02-L072 | 0,51 | Window | 1166Rau0000042125 | 1155Mak0000173532 | St | Fenstermakro, -SmartPart | 4.044 | 0 | 70 | 70 | 70 | 70 | 0 | 0.9 | 32 | - | F_Typ44 | AllplanAttributes (Fenster) - Sonnenschutztyp: Movable
Fenster | H2 Ebene +1 | 2.115 | 1.35 | WINDOW | 0 | E01 | 3.0 | Fenster | MainObject | SmartPartCompressed | 100 | 6.1 | 3.75 | FA-1FR-D-1S-E01-L087 | 0,35 | Window | 1166Rau0000033512 | 1155Mak0000003584 | St | Fenstermakro, -SmartPart | 1.99543 | 0 | 70 | 70 | 70 | 70 | 0 | 0.9 | 32 | - | F_Typ4A | AllplanAttributes (Fenster) - Sonnenschutztyp: Movable
Fenster | H2 Ebene +1 | 2.115 | 1.35 | WINDOW | 0 | E01 | 3.0 | Fenster | MainObject | SmartPartCompressed | 100 | 6.1 | 3.75 | FA-1FR-D-1S-E01-L088 | 0,35 | Window | 1166Rau0000033512 | 1155Mak0000003581 | St | Fenstermakro, -SmartPart | 1.99543 | 0 | 70 | 70 | 70 | 70 | 0 | 0.9 | 32 | - | F_Typ4A | AllplanAttributes (Fenster) - Sonnenschutztyp: Movable
Fenster | H2 Ebene +1 | 2.115 | 1.35 | WINDOW | 0 | E01 | 3.0 | Fenster | MainObject | SmartPartCompressed | 100 | 6.1 | 3.75 | FA-1FR-D-1S-E01-L090 | 0,35 | Window | 1166Rau0000033512 | 1155Mak0000003575 | St | Fenstermakro, -SmartPart | 1.99543 | 0 | 70 | 70 | 70 | 70 | 0 | 0.9 | 32 | - | F_Typ4A | AllplanAttributes (Fenster) - Sonnenschutztyp: Movable
Fenster | H2 Ebene +1 | 2.115 | 1.35 | WINDOW | 0 | E01 | 3.0 | Fenster | MainObject | SmartPartCompressed | 100 | 6.1 | 3.75 | FA-1FR-D-1S-E01-L091 | 0,35 | Window | 1166Rau0000033512 | 1155Mak0000003572 | St | Fenstermakro, -SmartPart | 1.99543 | 0 | 70 | 70 | 70 | 70 | 0 | 0.9 | 32 | - | F_Typ4A | AllplanAttributes (Fenster) - Sonnenschutztyp: Movable
Fenster | H2 Ebene +1 | 2.115 | 0.725 | WINDOW | 0 | E01 | 3.0 | Fenster | MainObject | SmartPartCompressed | 100 | 6.1 | 3.75 | FA-F-E01-L086 | 0,35 | Window | 1166Rau0000033131 | 1155Mak0000003587 | St | Fenstermakro, -SmartPart | 1.11442 | 0 | 70 | 70 | 70 | 70 | 0 | 0.9 | 32 | - | F_Typ6 | AllplanAttributes (Fenster) - Sonnenschutztyp: Movable
Fenster | H2 Ebene +1 | 2.115 | 0.725 | WINDOW | 0 | E01 | 3.0 | Fenster | MainObject | SmartPartCompressed | 100 | 6.1 | 3.75 | FA-F-E01-L054 | 0,35 | Window | 1166Rau0000033131 | 1155Mak2005808093 | St | Fenstermakro, -SmartPart | 1.11442 | 0 | 70 | 70 | 70 | 70 | 0 | 0.9 | 32 | - | F_Typ6 | AllplanAttributes (Fenster) - Sonnenschutztyp: Movable
Fenster | H2 Ebene +1 | 2.5 | 1.5 | WINDOW | 0 | E01 | 3.0 | Fenster | MainObject | SmartPartCompressed | 100 | 6.1 | 3.75 | FA-1FL-D-1S-E01-110 | 0,35 | Window | 1165Rau0000004782 | 1155Mak0000010247 | St | Fenstermakro, -SmartPart | 2.7344 | 0 | 70 | 70 | 70 | 70 | 0 | 0.9 | - | - | F_Typ28 | AllplanAttributes (Fenster) - Sonnenschutztyp: Movable
Fenster | H2 Ebene +1 | 2.5 | 1.25 | WINDOW | 0 | E01 | 3.0 | Fenster | MainObject | SmartPartCompressed | 100 | 6.1 | 3.75 | FA-1FR-D-1S-E01-124 | 0,35 | Window | 1165Rau0000004666 | 1155Mak0000086109 | St | Fenstermakro, -SmartPart | 2.1674 | 0 | 70 | 70 | 70 | 70 | 0 | 0.9 | 32 | - | F_Typ4 | AllplanAttributes (Fenster) - Sonnenschutztyp: Movable
Fenster | H2 Ebene +1 | 2.5 | 2.5 | WINDOW | 0 | E01 | 3.0 | Fenster | MainObject | SmartPartCompressed | 100 | 6.1 | 3.75 | FA-1FR-D-1S-X-E01-080 | 0,51 | Window | 1166Rau0000033560 | 1155Mak0813745895 | St | Fenstermakro, -SmartPart | 4.9494 | 0 | 70 | 70 | 70 | 70 | 0 | 0.9 | 35 | - | F_Typ2 | AllplanAttributes (Fenster) - Sonnenschutztyp: Movable
Fenster | H2 Ebene +1 | 2.5 | 2.5 | WINDOW | 0 | E01 | 3.0 | Fenster | MainObject | SmartPartCompressed | 100 | 6.1 | 3.75 | FA-1FL-D-1S-X-E01-079 | 0,51 | Window | 1166Rau0000033547 | 1155Mak0813745898 | St | Fenstermakro, -SmartPart | 4.9494 | 0 | 70 | 70 | 70 | 70 | 0 | 0.9 | 35 | - | F_Typ1 | Typ1 | AllplanAttributes (Fenster) - ash D_Plannummer: D1726; Sonnenschutztyp: Movable
Fenster | H2 Ebene +1 | 2.5 | 1.25 | WINDOW | 0 | E01 | 3.0 | Fenster | MainObject | SmartPartCompressed | 100 | 6.1 | 3.75 | FA-1FL-D-1S-E01-120 | 0,35 | Window | 1166Rau0000034150 | 1155Mak0000200020 | St | Fenstermakro, -SmartPart | 2.1674 | 0 | 70 | 70 | 70 | 70 | 0 | 0.9 | 32 | - | F_Typ3 | AllplanAttributes (Fenster) - Sonnenschutztyp: Movable
Fenster | H2 Ebene +1 | 2.5 | 1.25 | WINDOW | 0 | E01 | 3.0 | Fenster | MainObject | SmartPartCompressed | 100 | 6.1 | 3.75 | FA-1FL-D-1S-E01-121 | 0,35 | Window | 1166Rau0000034163 | 1155Mak0000200024 | St | Fenstermakro, -SmartPart | 2.1674 | 0 | 70 | 70 | 70 | 70 | 0 | 0.9 | 32 | - | F_Typ3 | AllplanAttributes (Fenster) - Sonnenschutztyp: Movable
Fenster | H2 Ebene +1 | 2.5 | 1.25 | WINDOW | 0 | E01 | 3.0 | Fenster | MainObject | SmartPartCompressed | 100 | 6.1 | 3.75 | FA-1FR-D-1S-E01-090 | 0,51 | Window | 1166Rau0000034085 | 1155Mak0813749801 | St | Fenstermakro, -SmartPart | 2.1674 | 0 | 70 | 70 | 70 | 70 | 0 | 0.9 | 32 | - | F_Typ4 | AllplanAttributes (Fenster) - Sonnenschutztyp: Movable
Fenster | H2 Ebene +1 | 2.5 | 2.5 | WINDOW | 0 | E01 | 3.0 | Fenster | MainObject | SmartPartCompressed | 100 | 6.1 | 3.75 | FA-1FR-D-1S-X-E01-127 | 0,51 | Window | 1166Rau0000033294 | 1155Mak0000012274 | St | Fenstermakro, -SmartPart | 4.9494 | 0 | 70 | 70 | 70 | 70 | 0 | 0.9 | 39 | - | F_Typ2 | AllplanAttributes (Fenster) - Sonnenschutztyp: Movable
Fenster | H2 Ebene +1 | 2.5 | 1.25 | WINDOW | 0 | E01 | 3.0 | Fenster | MainObject | SmartPartCompressed | 100 | 6.1 | 3.75 | FA-1FL-D-1S-E01-097 | 0,51 | Window | 1166Rau0000034085 | 1155Mak0000002210 | St | Fenstermakro, -SmartPart | 2.1674 | 0 | 70 | 70 | 70 | 70 | 0 | 0.9 | 32 | - | F_Typ3 | AllplanAttributes (Fenster) - Sonnenschutztyp: Movable
Fenster | H2 Ebene +1 | 2.5 | 2.5 | WINDOW | 0 | E01 | 3.0 | Fenster | MainObject | SmartPartCompressed | 100 | 6.1 | 3.75 | FA-1FL-D-1S-X-E01-132 | 0,51 | Window | 1166Rau0000033359 | 1155Mak0000191475 | St | Fenstermakro, -SmartPart | 4.9494 | 0 | 70 | 70 | 70 | 70 | 0 | 0.9 | 42 | - | F_Typ1 | Typ1 | AllplanAttributes (Fenster) - ash D_Plannummer: D1726; Sonnenschutztyp: Movable
Fenster | H2 Ebene +1 | 2.5 | 2.5 | WINDOW | 0 | E01 | 3.0 | Fenster | MainObject | SmartPartCompressed | 100 | 6.1 | 3.75 | FA-1FR-D-1S-X-E01-133 | 0,51 | Window | 1166Rau0000033372 | 1155Mak0000191472 | St | Fenstermakro, -SmartPart | 4.9494 | 0 | 70 | 70 | 70 | 70 | 0 | 0.9 | 42 | - | F_Typ2 | AllplanAttributes (Fenster) - Sonnenschutztyp: Movable
Fenster | H2 Ebene +1 | 2.5 | 2.5 | WINDOW | 0 | E01 | 3.0 | Fenster | MainObject | SmartPartCompressed | 100 | 6.1 | 3.75 | FA-1FL-D-1S-X-E01-116 | 0,51 | Window | 1166Rau0000034497 | 1155Mak0000012299 | St | Fenstermakro, -SmartPart | 4.9494 | 0 | 70 | 70 | 70 | 70 | 0 | 0.9 | 35 | - | F_Typ1 | Typ1 | AllplanAttributes (Fenster) - ash D_Plannummer: D1726; Sonnenschutztyp: Movable
Fenster | H2 Ebene +1 | 2.5 | 2.5 | WINDOW | 0 | E01 | 3.0 | Fenster | MainObject | SmartPartCompressed | 100 | 6.1 | 3.75 | FA-1FR-D-1S-X-E01-117 | 0,51 | Window | 1166Rau0000034521 | 1155Mak0000012302 | St | Fenstermakro, -SmartPart | 4.9494 | 0 | 70 | 70 | 70 | 70 | 0 | 0.9 | 35 | - | F_Typ2 | AllplanAttributes (Fenster) - Sonnenschutztyp: Movable
Fenster | H2 Ebene +1 | 1.12 | 2.3945 | WINDOW | 0 |  | 2.2 | Fenster | MainObject | SmartPartCompressed | 100 | 4.1 |  |  |  |  |  | 1155Mak2005679113 | St | Fenstermakro, -SmartPart | 2.2745 | 0 | 60 | 60 | 60 | 60 |  | 0 |  |  | Codetext | AllplanAttributes (Fenster) - Codetext: Codetext; Gewerk: Metallbau-, Schlosserarbeiten; Funktion: Funktion; Glasart: Glasart; Typ: Typ; Fluchtweg: no; Pset_DoorWindowGlazingType - Shading Coefficient: 0; Pset_WindowCommon - Status: NEW; IsExternal: yes; SmokeStop: no
Fenster | H2 Ebene +1 | 1.12 | 2.418 | WINDOW | 0 |  | 2.2 | Fenster | MainObject | SmartPartCompressed | 100 | 4.1 |  |  |  |  |  | 1155Mak2005680080 | St | Fenstermakro, -SmartPart | 2.298 | 0 | 60 | 60 | 60 | 60 |  | 0 |  |  | Codetext | AllplanAttributes (Fenster) - Codetext: Codetext; Gewerk: Metallbau-, Schlosserarbeiten; Funktion: Funktion; Glasart: Glasart; Typ: Typ; Fluchtweg: no; Pset_DoorWindowGlazingType - Shading Coefficient: 0; Pset_WindowCommon - Status: NEW; IsExternal: yes; SmokeStop: no
Fenster | H2 Ebene +1 | 2.5 | 1.65 | WINDOW | 0 | E01 | 3.0 | Fenster | MainObject | SmartPartCompressed | 100 | 6.1 | 3.75 | FA-1FL-D-1S-E01-122 | 0,35 | Window | 1165Rau0000004749 | 1155Mak0000124251 | St | Fenstermakro, -SmartPart | 3.0734 | 0 | 70 | 70 | 70 | 70 | 0 | 0.9 | 32 | - | F_Typ28 | AllplanAttributes (Fenster) - Sonnenschutztyp: Movable
Fenster | H2 Ebene +1 | 2.5 | 3.92258 | WINDOW | 0 | E01 | 3.0 | Fenster | MainObject | SmartPartCompressed | 100 | 7.2 | 3.75 | FA-1FL-D-2S-E01-123 | 0,35 | Window | 1165Rau0000004749 | 1155Mak0000123665 | St | Fenstermakro, -SmartPart | 8.33748 | 0 | 70 | 70 | 70 | 70 | 0 | 0.9 | 32 | - | F_Typ29 | AllplanAttributes (Fenster) - Sonnenschutztyp: Movable
Fenster | H2 Ebene +1 | 2.26 | 1.84802 | WINDOW | 0 | E01 | 3.0 | Fenster | MainObject | SmartPartCompressed | 100 | 6.1 | 3.75 | FA-1FL-D-1S-X-E01-126 | 0,35 | Window | 1165Rau0000004808 | 1155Mak2005702247 | St | Fenstermakro, -SmartPart | 3.1518 | 0 | 70 | 70 | 70 | 70 | 0 | 0.9 | - | - | F_Typ10
Fenster | H2 Ebene +1 | 2.26 | 1.8145 | WINDOW | 0 | E01 | 3.0 | Fenster | MainObject | SmartPartCompressed | 100 | 6.1 | 3.75 | FA-1FL-D-1S-X-E01-119 | 0,35 | Window | 1165Rau0000004819 | 1155Mak2005704457 | St | Fenstermakro, -SmartPart | 3.08409 | 0 | 70 | 70 | 70 | 70 | 0 | 0.9 | - | - | F_Typ9 | AllplanAttributes (Fenster) - Sonnenschutztyp: Movable
Fenster | H2 Ebene +1 | 2.5 | 2.5 | WINDOW | 0 | E01 | 3.0 | Fenster | MainObject | SmartPartCompressed | 100 | 6.1 | 3.75 | FA-1FL-D-1S-X-E01-118 | 0,51 | Window | 1166Rau0000034545 | 1155Mak0000012305 | St | Fenstermakro, -SmartPart | 4.9494 | 0 | 70 | 70 | 70 | 70 | 0 | 0.9 | 35 | - | F_Typ1 | Typ1 | AllplanAttributes (Fenster) - ash D_Plannummer: D1726; Sonnenschutztyp: Movable
Fenster | H2 Ebene +1 | 2.5 | 2.28 | WINDOW | 0 | E01 | 3.0 | Fenster | MainObject | SmartPartCompressed | 100 | 7.2 | 3.75 | FA-F-E01-134 | 0,49 | Window | 1165Rau0000004651 | 1155Mak0000191873 | St | Fenstermakro, -SmartPart | 4.8852 | 0 | 70 | 70 | 70 | 70 | EI 60 | 2 | - | - | F_Typ8 | AllplanAttributes (Fenster) - Sonnenschutztyp: Movable; Gewerk: Zimmer- und Holzbauarbeiten; Selbstschließend: no; ash T_Zulage Schachttür: no; ash T_Dichtschließend: no; ash T_Feststellanlage (FSA): -; ash T_nicht abschließbar: no; Pset_WindowCommon - SmokeStop: yes
Fenster | H2 Ebene +1 | 2.115 | 1.45 | WINDOW | 0 | E01 | 3.0 | Fenster | MainObject | SmartPartCompressed | 100 | 6.1 | 3.75 | FA-1FL-D-1S-E01-L047d | 0,35 | Window | 1166Rau0000033512 | 1155Mak2005822854 | St | Fenstermakro, -SmartPart | 2.18293 | 0 | 70 | 70 | 70 | 70 | 0 | 0.9 | 32 | - | F_Typ3A | Typ3 | AllplanAttributes (Fenster) - ash D_Plannummer: D1727; Sonnenschutztyp: Movable
Fenster | H2 Ebene +1 | 2.115 | 1.35 | WINDOW | 0 | E01 | 3.0 | Fenster | MainObject | SmartPartCompressed | 100 | 6.1 | 3.75 | FA-1FL-D-1S-E01-L047c | 0,35 | Window | 1166Rau0000033512 | 1155Mak2005776502 | St | Fenstermakro, -SmartPart | 1.99543 | 0 | 70 | 70 | 70 | 70 | 0 | 0.9 | 32 | - | F_Typ3A | Typ3 | AllplanAttributes (Fenster) - ash D_Plannummer: D1727; Sonnenschutztyp: Movable
Fenster | H2 Ebene +1 | 2.115 | 1.35 | WINDOW | 0 | E01 | 3.0 | Fenster | MainObject | SmartPartCompressed | 100 | 6.1 | 3.75 | FA-1FL-D-1S-E01-L047b | 0,35 | Window | 1166Rau0000033512 | 1155Mak2005776656 | St | Fenstermakro, -SmartPart | 1.99543 | 0 | 70 | 70 | 70 | 70 | 0 | 0.9 | 32 | - | F_Typ3A | Typ3 | AllplanAttributes (Fenster) - ash D_Plannummer: D1727; Sonnenschutztyp: Movable
Fenster | H2 Ebene +1 | 2.115 | 1.35 | WINDOW | 0 | E01 | 3.0 | Fenster | MainObject | SmartPartCompressed | 100 | 6.1 | 3.75 | FA-1FL-D-1S-E01-L047a | 0,35 | Window | 1166Rau0000033512 | 1155Mak2005776765 | St | Fenstermakro, -SmartPart | 1.99543 | 0 | 70 | 70 | 70 | 70 | 0 | 0.9 | 32 | - | F_Typ3A | Typ3 | AllplanAttributes (Fenster) - ash D_Plannummer: D1727; Sonnenschutztyp: Movable
Fenster | H2 Ebene +1 | 2.115 | 1.45 | WINDOW | 0 | E01 | 3.0 | Fenster | MainObject | SmartPartCompressed | 100 | 6.1 | 3.75 | FA-1FR-D-1S-E01-L055a | 0,35 | Window | 1166Rau0000033512 | 1155Mak2005820865 | St | Fenstermakro, -SmartPart | 2.18293 | 0 | 70 | 70 | 70 | 70 | 0 | 0.9 | 32 | - | F_Typ4A | AllplanAttributes (Fenster) - Sonnenschutztyp: Movable
Fenster | H2 Ebene +1 | 2.115 | 1.35 | WINDOW | 0 | E01 | 3.0 | Fenster | MainObject | SmartPartCompressed | 100 | 6.1 | 3.75 | FA-1FR-D-1S-E01-L055b | 0,35 | Window | 1166Rau0000033512 | 1155Mak2005776997 | St | Fenstermakro, -SmartPart | 1.99543 | 0 | 70 | 70 | 70 | 70 | 0 | 0.9 | 32 | - | F_Typ4A | AllplanAttributes (Fenster) - Sonnenschutztyp: Movable
Fenster | H2 Ebene +1 | 2.115 | 1.35 | WINDOW | 0 | E01 | 3.0 | Fenster | MainObject | SmartPartCompressed | 100 | 6.1 | 3.75 | FA-1FR-D-1S-E01-L055c | 0,35 | Window | 1166Rau0000033512 | 1155Mak2005777101 | St | Fenstermakro, -SmartPart | 1.99543 | 0 | 70 | 70 | 70 | 70 | 0 | 0.9 | 32 | - | F_Typ4A | AllplanAttributes (Fenster) - Sonnenschutztyp: Movable
Fenster | H2 Ebene +1 | 2.115 | 1.35 | WINDOW | 0 | E01 | 3.0 | Fenster | MainObject | SmartPartCompressed | 100 | 6.1 | 3.75 | FA-1FR-D-1S-E01-L055d | 0,35 | Window | 1166Rau0000033512 | 1155Mak2005777205 | St | Fenstermakro, -SmartPart | 1.99543 | 0 | 70 | 70 | 70 | 70 | 0 | 0.9 | 32 | - | F_Typ4A | AllplanAttributes (Fenster) - Sonnenschutztyp: Movable
Fenster | H2 Ebene +1 | 2.115 | 1.35 | WINDOW | 0 | E01 | 3.0 | Fenster | MainObject | SmartPartCompressed | 100 | 6.1 | 3.75 | FA-1FL-D-1S-E01-L068 | 0,35 | Window | 1166Rau0000033512 | 1155Mak2005796725 | St | Fenstermakro, -SmartPart | 1.99543 | 0 | 70 | 70 | 70 | 70 | 0 | 0.9 | 32 | - | F_Typ3A | Typ3 | AllplanAttributes (Fenster) - ash D_Plannummer: D1727; Sonnenschutztyp: Movable
Fenster | H2 Ebene +1 | 2.115 | 1.35 | WINDOW | 0 | E01 | 3.0 | Fenster | MainObject | SmartPartCompressed | 100 | 6.1 | 3.75 | FA-1FR-D-1S-E01-L076 | 0,35 | Window | 1166Rau0000033512 | 1155Mak2005779183 | St | Fenstermakro, -SmartPart | 1.99543 | 0 | 70 | 70 | 70 | 70 | 0 | 0.9 | 32 | - | F_Typ4A | AllplanAttributes (Fenster) - Sonnenschutztyp: Movable
Fenster | H2 Ebene +1 | 2.115 | 1.35 | WINDOW | 0 | E01 | 3.0 | Fenster | MainObject | SmartPartCompressed | 100 | 6.1 | 3.75 | FA-1FL-D-1S-E01-L073 | 0,35 | Window | 1166Rau0000033512 | 1155Mak2005785007 | St | Fenstermakro, -SmartPart | 1.99543 | 0 | 70 | 70 | 70 | 70 | 0 | 0.9 | 32 | - | F_Typ3A | Typ3 | AllplanAttributes (Fenster) - ash D_Plannummer: D1727; Sonnenschutztyp: Movable
Fenster | H2 Ebene +1 | 2.115 | 1.35 | WINDOW | 0 | E01 | 3.0 | Fenster | MainObject | SmartPartCompressed | 100 | 6.1 | 3.75 | FA-1FL-D-1S-E01-L074 | 0,35 | Window | 1166Rau0000033512 | 1155Mak2005784933 | St | Fenstermakro, -SmartPart | 1.99543 | 0 | 70 | 70 | 70 | 70 | 0 | 0.9 | 32 | - | F_Typ3A | Typ3 | AllplanAttributes (Fenster) - ash D_Plannummer: D1727; Sonnenschutztyp: Movable
Fenster | H2 Ebene +1 | 2.115 | 1.35 | WINDOW | 0 | E01 | 3.0 | Fenster | MainObject | SmartPartCompressed | 100 | 6.1 | 3.75 | FA-1FL-D-1S-E01-L063 | 0,35 | Window | 1166Rau0000033512 | 1155Mak2005797952 | St | Fenstermakro, -SmartPart | 1.99543 | 0 | 70 | 70 | 70 | 70 | 0 | 0.9 | 32 | - | F_Typ3A | Typ3 | AllplanAttributes (Fenster) - ash D_Plannummer: D1727; Sonnenschutztyp: Movable
Fenster | H2 Ebene +1 | 2.115 | 1.35 | WINDOW | 0 | E01 | 3.0 | Fenster | MainObject | SmartPartCompressed | 100 | 6.1 | 3.75 | FA-1FL-D-1S-E01-L064 | 0,35 | Window | 1166Rau0000033512 | 1155Mak2005798276 | St | Fenstermakro, -SmartPart | 1.99543 | 0 | 70 | 70 | 70 | 70 | 0 | 0.9 | 32 | - | F_Typ3A | Typ3 | AllplanAttributes (Fenster) - ash D_Plannummer: D1727; Sonnenschutztyp: Movable
Fenster | H2 Ebene +1 | 2.115 | 1.35 | WINDOW | 0 | E01 | 3.0 | Fenster | MainObject | SmartPartCompressed | 100 | 6.1 | 3.75 | FA-1FL-D-1S-E01-L066 | 0,35 | Window | 1166Rau0000033512 | 1155Mak2005798365 | St | Fenstermakro, -SmartPart | 1.99543 | 0 | 70 | 70 | 70 | 70 | 0 | 0.9 | 32 | - | F_Typ3A | Typ3 | AllplanAttributes (Fenster) - ash D_Plannummer: D1727; Sonnenschutztyp: Movable
Fenster | H2 Ebene +1 | 2.115 | 1.35 | WINDOW | 0 | E01 | 3.0 | Fenster | MainObject | SmartPartCompressed | 100 | 6.1 | 3.75 | FA-1FL-D-1S-E01-L066a | 0,35 | Window | 1166Rau0000033512 | 1155Mak2005798454 | St | Fenstermakro, -SmartPart | 1.99543 | 0 | 70 | 70 | 70 | 70 | 0 | 0.9 | 32 | - | F_Typ3A | Typ3 | AllplanAttributes (Fenster) - ash D_Plannummer: D1727; Sonnenschutztyp: Movable
Fenster | H2 Ebene +1 | 2.115 | 2.6 | WINDOW | 0 | E01 | 3.0 | Fenster | MainObject | SmartPartCompressed | 100 | 6.1 | 3.75 | FA-2FLR-D-1S-E01-L065 | 0,35 | Window | 1166Rau0000033512 | 1155Mak2005798543 | St | Fenstermakro, -SmartPart | 4.044 | 0 | 70 | 70 | 70 | 70 | 0 | 0.9 | 32 | - | F_Typ44 | AllplanAttributes (Fenster) - Sonnenschutztyp: Movable
Fenster | H2 Ebene +1 | 2.115 | 1.35 | WINDOW | 0 | E01 | 3.0 | Fenster | MainObject | SmartPartCompressed | 100 | 6.1 | 3.75 | FA-1FL-D-1S-E01-L084 | 0,35 | Window | 1166Rau0000033512 | 1155Mak2005802558 | St | Fenstermakro, -SmartPart | 1.99543 | 0 | 70 | 70 | 70 | 70 | 0 | 0.9 | 32 | - | F_Typ3A | Typ3 | AllplanAttributes (Fenster) - ash D_Plannummer: D1727; Sonnenschutztyp: Movable
Fenster | H2 Ebene +1 | 2.115 | 1.35 | WINDOW | 0 | E01 | 3.0 | Fenster | MainObject | SmartPartCompressed | 100 | 6.1 | 3.75 | FA-1FL-D-1S-E01-L083 | 0,35 | Window | 1166Rau0000033512 | 1155Mak2005802652 | St | Fenstermakro, -SmartPart | 1.99543 | 0 | 70 | 70 | 70 | 70 | 0 | 0.9 | 32 | - | F_Typ3A | Typ3 | AllplanAttributes (Fenster) - ash D_Plannummer: D1727; Sonnenschutztyp: Movable
Fenster | H2 Ebene +1 | 2.115 | 1.35 | WINDOW | 0 | E01 | 3.0 | Fenster | MainObject | SmartPartCompressed | 100 | 6.1 | 3.75 | FA-1FL-D-1S-E01-L082 | 0,35 | Window | 1166Rau0000033512 | 1155Mak2005802746 | St | Fenstermakro, -SmartPart | 1.99543 | 0 | 70 | 70 | 70 | 70 | 0 | 0.9 | 32 | - | F_Typ3A | Typ3 | AllplanAttributes (Fenster) - ash D_Plannummer: D1727; Sonnenschutztyp: Movable
Fenster | H2 Ebene +1 | 2.115 | 1.35 | WINDOW | 0 | E01 | 3.0 | Fenster | MainObject | SmartPartCompressed | 100 | 6.1 | 3.75 | FA-1FL-D-1S-E01-L079 | 0,35 | Window | 1166Rau0000033512 | 1155Mak2005802419 | St | Fenstermakro, -SmartPart | 1.99543 | 0 | 70 | 70 | 70 | 70 | 0 | 0.9 | 32 | - | F_Typ3A | Typ3 | AllplanAttributes (Fenster) - ash D_Plannummer: D1727; Sonnenschutztyp: Movable
Fenster | H2 Ebene +1 | 2.115 | 1.35 | WINDOW | 0 | E01 | 3.0 | Fenster | MainObject | SmartPartCompressed | 100 | 6.1 | 3.75 | FA-1FL-D-1S-E01-L078 | 0,35 | Window | 1166Rau0000033512 | 1155Mak2005802076 | St | Fenstermakro, -SmartPart | 1.99543 | 0 | 70 | 70 | 70 | 70 | 0 | 0.9 | 32 | - | F_Typ3A | AllplanAttributes (Fenster) - Sonnenschutztyp: Movable
Fenster | H2 Ebene +1 | 2.115 | 1.35 | WINDOW | 0 | E01 | 3.0 | Fenster | MainObject | SmartPartCompressed | 100 | 6.1 | 3.75 | FA-1FR-D-1S-E01-L077b | 0,35 | Window | 1166Rau0000033512 | 1155Mak2005800349 | St | Fenstermakro, -SmartPart | 1.99543 | 0 | 70 | 70 | 70 | 70 | 0 | 0.9 | 32 | - | F_Typ4A | AllplanAttributes (Fenster) - Sonnenschutztyp: Movable
Fenster | H2 Ebene +1 | 2.115 | 1.35 | WINDOW | 0 | E01 | 3.0 | Fenster | MainObject | SmartPartCompressed | 100 | 6.1 | 3.75 | FA-1FR-D-1S-E01-L077c | 0,35 | Window | 1166Rau0000033512 | 1155Mak2005800545 | St | Fenstermakro, -SmartPart | 1.99543 | 0 | 70 | 70 | 70 | 70 | 0 | 0.9 | 32 | - | F_Typ4A | AllplanAttributes (Fenster) - Sonnenschutztyp: Movable
Fenster | H2 Ebene +1 | 2.115 | 1.35 | WINDOW | 0 | E01 | 3.0 | Fenster | MainObject | SmartPartCompressed | 100 | 6.1 | 3.75 | FA-1FR-D-1S-E01-L077d | 0,35 | Window | 1166Rau0000033512 | 1155Mak2005800654 | St | Fenstermakro, -SmartPart | 1.99543 | 0 | 70 | 70 | 70 | 70 | 0 | 0.9 | 32 | - | F_Typ4A | AllplanAttributes (Fenster) - Sonnenschutztyp: Movable
Fenster | H2 Ebene +1 | 2.115 | 1.45 | WINDOW | 0 | E01 | 3.0 | Fenster | MainObject | SmartPartCompressed | 100 | 6.1 | 3.75 | FA-1FR-D-1S-E01-L077a | 0,35 | Window | 1166Rau0000033512 | 1155Mak2005800240 | St | Fenstermakro, -SmartPart | 2.18293 | 0 | 70 | 70 | 70 | 70 | 0 | 0.9 | 32 | - | F_Typ4A | AllplanAttributes (Fenster) - Sonnenschutztyp: Movable
Fenster | H2 Ebene +1 | 2.115 | 1.45 | WINDOW | 0 | E01 | 3.0 | Fenster | MainObject | SmartPartCompressed | 100 | 6.1 | 3.75 | FA-1FL-D-1S-E01-L085d | 0,35 | Window | 1166Rau0000033512 | 1155Mak2005804377 | St | Fenstermakro, -SmartPart | 2.18293 | 0 | 70 | 70 | 70 | 70 | 0 | 0.9 | 32 | - | F_Typ3A | Typ3 | AllplanAttributes (Fenster) - ash D_Plannummer: D1727; Sonnenschutztyp: Movable
Fenster | H2 Ebene +1 | 2.115 | 1.35 | WINDOW | 0 | E01 | 3.0 | Fenster | MainObject | SmartPartCompressed | 100 | 6.1 | 3.75 | FA-1FL-D-1S-E01-L085a | 0,35 | Window | 1166Rau0000033512 | 1155Mak2005804065 | St | Fenstermakro, -SmartPart | 1.99543 | 0 | 70 | 70 | 70 | 70 | 0 | 0.9 | 32 | - | F_Typ3A | Typ3 | AllplanAttributes (Fenster) - ash D_Plannummer: D1727; Sonnenschutztyp: Movable
Fenster | H2 Ebene +1 | 2.115 | 1.35 | WINDOW | 0 | E01 | 3.0 | Fenster | MainObject | SmartPartCompressed | 100 | 6.1 | 3.75 | FA-1FL-D-1S-E01-L085b | 0,35 | Window | 1166Rau0000033512 | 1155Mak2005804169 | St | Fenstermakro, -SmartPart | 1.99543 | 0 | 70 | 70 | 70 | 70 | 0 | 0.9 | 32 | - | F_Typ3A | Typ3 | AllplanAttributes (Fenster) - ash D_Plannummer: D1727; Sonnenschutztyp: Movable
Fenster | H2 Ebene +1 | 2.115 | 1.35 | WINDOW | 0 | E01 | 3.0 | Fenster | MainObject | SmartPartCompressed | 100 | 6.1 | 3.75 | FA-1FL-D-1S-E01-L085c | 0,35 | Window | 1166Rau0000033512 | 1155Mak2005804273 | St | Fenstermakro, -SmartPart | 1.99543 | 0 | 70 | 70 | 70 | 70 | 0 | 0.9 | 32 | - | F_Typ3A | Typ3 | AllplanAttributes (Fenster) - ash D_Plannummer: D1727; Sonnenschutztyp: Movable
Fenster | H2 Ebene +1 | 2.5 | 2.5 | WINDOW | 0 | E01 | 3.0 | Fenster | MainObject | SmartPartCompressed | 100 | 6.1 | 3.75 | FA-1FR-D-1S-X-E01-108 | 0,51 | Window | 1166Rau0000033940 | 1155Mak2005813678 | St | Fenstermakro, -SmartPart | 4.9494 | 0 | 70 | 70 | 70 | 70 | 0 | 0.9 | 32 | - | F_Typ2 | AllplanAttributes (Fenster) - Sonnenschutztyp: Movable
Fenster | H2 Ebene +1 | 2.5 | 2.5 | WINDOW | 0 | E01 | 3.0 | Fenster | MainObject | SmartPartCompressed | 100 | 6.1 | 3.75 | FA-1FL-D-1S-X-E01-107 | 0,51 | Window | 1166Rau0000033927 | 1155Mak2005813631 | St | Fenstermakro, -SmartPart | 4.9494 | 0 | 70 | 70 | 70 | 70 | 0 | 0.9 | 32 | - | F_Typ1 | Typ1 | AllplanAttributes (Fenster) - ash D_Plannummer: D1726; Sonnenschutztyp: Movable
Fenster | H2 Ebene +1 | 2.5 | 2.5 | WINDOW | 0 | E01 | 3.0 | Fenster | MainObject | SmartPartCompressed | 100 | 6.1 | 3.75 | FA-1FR-D-1S-X-E01-102 | 0,51 | Window | 1166Rau0000033862 | 1155Mak2005818954 | St | Fenstermakro, -SmartPart | 4.9494 | 0 | 70 | 70 | 70 | 70 | 0 | 0.9 | 32 | - | F_Typ2 | AllplanAttributes (Fenster) - Sonnenschutztyp: Movable
Fenster | H2 Ebene +1 | 2.5 | 2.5 | WINDOW | 0 | E01 | 3.0 | Fenster | MainObject | SmartPartCompressed | 100 | 6.1 | 3.75 | FA-1FR-D-1S-X-E01-104 | 0,51 | Window | 1166Rau0000033888 | 1155Mak2005818928 | St | Fenstermakro, -SmartPart | 4.9494 | 0 | 70 | 70 | 70 | 70 | 0 | 0.9 | 32 | - | F_Typ2 | AllplanAttributes (Fenster) - Sonnenschutztyp: Movable
Fenster | H2 Ebene +1 | 2.5 | 2.5 | WINDOW | 0 | E01 | 3.0 | Fenster | MainObject | SmartPartCompressed | 100 | 6.1 | 3.75 | FA-1FL-D-1S-X-E01-103 | 0,51 | Window | 1166Rau0000033875 | 1155Mak2005819004 | St | Fenstermakro, -SmartPart | 4.9494 | 0 | 70 | 70 | 70 | 70 | 0 | 0.9 | 32 | - | F_Typ1 | Typ1 | AllplanAttributes (Fenster) - ash D_Plannummer: D1726; Sonnenschutztyp: Movable
Fenster | H2 Ebene +1 | 2.5 | 2.5 | WINDOW | 0 | E01 | 3.0 | Fenster | MainObject | SmartPartCompressed | 100 | 6.1 | 3.75 | FA-1FL-D-1S-X-E01-105 | 0,51 | Window | 1166Rau0000033901 | 1155Mak2005819099 | St | Fenstermakro, -SmartPart | 4.9494 | 0 | 70 | 70 | 70 | 70 | 0 | 0.9 | 32 | - | F_Typ1 | Typ1 | AllplanAttributes (Fenster) - ash D_Plannummer: D1726; Sonnenschutztyp: Movable
Fenster | H2 Ebene +1 | 2.5 | 2.5 | WINDOW | 0 | E01 | 3.0 | Fenster | MainObject | SmartPartCompressed | 100 | 6.1 | 3.75 | FA-1FR-D-1S-X-E01-106 | 0,51 | Window | 1166Rau0000033914 | 1155Mak2005819096 | St | Fenstermakro, -SmartPart | 4.9494 | 0 | 70 | 70 | 70 | 70 | 0 | 0.9 | 32 | - | F_Typ2 | AllplanAttributes (Fenster) - Sonnenschutztyp: Movable
Fenster | H2 Ebene +1 | 2.755 | 2.418 | WINDOW | 0 |  | 2.2 | Fenster | MainObject | SmartPartCompressed | 100 | 4.1 |  |  |  |  |  | 1155Mak2005680067 | St | Fenstermakro, -SmartPart | 5.47767 | 0 | 100 | 0 | 0 | 0 |  | 0 |  |  | Codetext | AllplanAttributes (Fenster) - Codetext: Codetext; Gewerk: Metallbau-, Schlosserarbeiten; Funktion: Funktion; Glasart: Glasart; Typ: Typ; Fluchtweg: no; Pset_DoorWindowGlazingType - Shading Coefficient: 0; Pset_WindowCommon - Status: NEW; IsExternal: yes; SmokeStop: no
Fenster | H2 Ebene +1 | 2.755 | 2.3945 | WINDOW | 0 |  | 2.2 | Fenster | MainObject | SmartPartCompressed | 100 | 4.1 |  |  |  |  |  | 1155Mak2005679272 | St | Fenstermakro, -SmartPart | 5.41857 | 0 | 100 | 0 | 0 | 0 |  | 0 |  |  | Codetext | AllplanAttributes (Fenster) - Codetext: Codetext; Gewerk: Metallbau-, Schlosserarbeiten; Funktion: Funktion; Glasart: Glasart; Typ: Typ; Fluchtweg: no; Pset_DoorWindowGlazingType - Shading Coefficient: 0; Pset_WindowCommon - Status: NEW; IsExternal: yes; SmokeStop: no
Fenster | H2 Ebene +1 | 2.5 | 1.25 | WINDOW | 0 | E01 | 3.0 | Fenster | MainObject | SmartPartCompressed | 100 | 6.1 | 3.75 | FA-1F-K-E01-125 | 0,35 | Window | 1166Rau0000033118 | 1155Mak0000084948 | St | Fenstermakro, -SmartPart | 2.1674 | 0 | 70 | 70 | 70 | 70 | 0 | 0.9 | 32 | - | F_Typ4 | AllplanAttributes (Fenster) - Sonnenschutztyp: Movable
Fenster | H2 Ebene +1 | 1.31 | 1.6 | WINDOW | 0 | E00 | 3.0 | Fenster | MainObject | SmartPartCompressed | 100 | 7.2 | 0 | FI-E00-012-001-002 |  | Window | 1116Rau0000066462 | 1163Mak0814462001 | St | Fenstermakro, -SmartPart | 1.7082 | 0 | 70 | 70 | 70 | 70 | EI 30 | AllplanAttributes (Fenster) - Gewerk: Zimmer- und Holzbauarbeiten; Selbstschließend: no; ash T_Zulage Schachttür: no; ash T_Dichtschließend: no; ash T_Feststellanlage (FSA): -; ash T_nicht abschließbar: yes; ash T_Schallschutz: 24 dB; Positionsnummer_Text: S68; Pset_WindowCommon - SmokeStop: yes; AllplanAttributes (TGR 1.5) - Codetext: Typ; V6: 0 m; V7: 0 m; V8: 0 m; V9: 0; Programmversion: 3.1; Objektname: TGR-Makro; Text1: PlanNo.; Bezeichnung: TGR 1.5; Plugin_Bezeichnung: MainObject; Plugin_Objektname: SmartPartCompressed; Gesamtlänge: 8.855; Version: 1.5; OKFF: 0; ash T_Türprofilnummer: 7; Positionsnummer_Text: S68; P_ID: 1115Rau0000005189; Allright_Bauteil_ID: 1163Mak0814462205; Abrechnungsart: St
Fenster | H2 Ebene +1 | 1.18 | 1.0525 | WINDOW | 0 | E01 | 3.0 | Fenster | MainObject | SmartPartCompressed | 100 | 7.2 | 3.75 |  |  | Window | 1166Rau0000042125 | 1163Mak0814705963 | St | Fenstermakro, -SmartPart | 0.948997 | 0 | 70 | 70 | 70 | 70 | AllplanAttributes (Fenster) - Gewerk: Zimmer- und Holzbauarbeiten; Selbstschließend: no; ash T_Zulage Schachttür: no; ash T_Dichtschließend: no; ash T_Feststellanlage (FSA): -; ash T_nicht abschließbar: no; ash T_Schallschutz: -; Pset_WindowCommon - SmokeStop: yes
Fenster | H2 Ebene +1 | 1.18 | 1.0525 | WINDOW | 0 | E01 | 3.0 | Fenster | MainObject | SmartPartCompressed | 100 | 7.2 | 3.75 |  |  | Window | 1166Rau0000042125 | 1163Mak0814705991 | St | Fenstermakro, -SmartPart | 0.948995 | 0 | 70 | 70 | 70 | 70 | AllplanAttributes (Fenster) - Gewerk: Zimmer- und Holzbauarbeiten; Selbstschließend: no; ash T_Zulage Schachttür: no; ash T_Dichtschließend: no; ash T_Feststellanlage (FSA): -; ash T_nicht abschließbar: no; ash T_Schallschutz: -; Pset_WindowCommon - SmokeStop: yes
Fenster | H2 Ebene +1 | 1.18 | 1.92301 | WINDOW | 0 | E01 | 3.0 | Fenster | MainObject | SmartPartCompressed | 100 | 7.2 | 3.75 |  |  | Window | 1166Rau0000042125 | 1163Mak0814705984 | St | Fenstermakro, -SmartPart | 1.85433 | 0 | 70 | 70 | 70 | 70 | AllplanAttributes (Fenster) - Gewerk: Zimmer- und Holzbauarbeiten; Selbstschließend: no; ash T_Zulage Schachttür: no; ash T_Dichtschließend: no; ash T_Feststellanlage (FSA): -; ash T_nicht abschließbar: no; ash T_Schallschutz: -; Pset_WindowCommon - SmokeStop: yes
Fenster | H2 Ebene +1 | 1.51 | 2.185 | WINDOW | 0 | E01 | 3.0 | Fenster | MainObject | SmartPartCompressed | 100 | 7.2 | 3.75 |  |  | Window | 1166Rau0000042125 | 1163Mak0814705988 | St | Fenstermakro, -SmartPart | 2.80165 | 0 | 70 | 70 | 70 | 70 |  |  |  |  |  | D6 | AllplanAttributes (Fenster) - ash D_Plannummer: 1684; Gewerk: Zimmer- und Holzbauarbeiten; Selbstschließend: no; ash T_Zulage Schachttür: no; ash T_Dichtschließend: no; ash T_Feststellanlage (FSA): -; ash T_nicht abschließbar: no; ash T_Schallschutz: -; Pset_WindowCommon - SmokeStop: yes
Fenster | H2 Ebene +1 | 1.31 | 1.6 | WINDOW | 0 | E01 | 3.0 | Fenster | MainObject | SmartPartCompressed | 100 | 7.2 | 3.75 |  |  | Window | 1166Rau0000042125 | 1163Mak0814612120 | St | Fenstermakro, -SmartPart | 1.7082 | 0 | 70 | 70 | 70 | 70 | EI 30 | AllplanAttributes (Fenster) - Gewerk: Zimmer- und Holzbauarbeiten; Selbstschließend: no; ash T_Zulage Schachttür: no; ash T_Dichtschließend: no; ash T_Feststellanlage (FSA): -; ash T_nicht abschließbar: yes; ash T_Schallschutz: 24 dB; Positionsnummer_Text: U100; Pset_WindowCommon - SmokeStop: yes
Fenster | H2 Ebene +1 | 1.88 | 0.64994 | WINDOW | 0 | E01 | 3.0 | Fenster | MainObject | SmartPartCompressed | 100 | 7.2 | 3.75 |  |  | Window | 1166Rau0000042125 | 1163Mak0814111862 | St | Fenstermakro, -SmartPart | 1.22189 | 0 | 0 | 0 | 0 | 0 | EI 30 | AllplanAttributes (Fenster) - Gewerk: Zimmer- und Holzbauarbeiten; Selbstschließend: no; ash T_Zulage Schachttür: no; ash T_Dichtschließend: no; ash T_Feststellanlage (FSA): -; ash T_nicht abschließbar: yes; ash T_Schallschutz: 24 dB; Positionsnummer_Text: U100; Pset_WindowCommon - SmokeStop: yes
Fenster | H2 Ebene +1 | 1.18 | 3.095 | WINDOW | 0 | E01 | 3.0 | Fenster | MainObject | SmartPartCompressed | 100 | 7.2 | 3.75 |  |  | Window | 1166Rau0000042125 | 1163Mak0814705961 | St | Fenstermakro, -SmartPart | 3.0732 | 0 | 70 | 70 | 70 | 70 |  |  |  |  |  | D6 | AllplanAttributes (Fenster) - ash D_Plannummer: 1684; Gewerk: Zimmer- und Holzbauarbeiten; Selbstschließend: no; ash T_Zulage Schachttür: no; ash T_Dichtschließend: no; ash T_Feststellanlage (FSA): -; ash T_nicht abschließbar: no; ash T_Schallschutz: -; Pset_WindowCommon - SmokeStop: yes
Fenster | H2 Ebene +1 | 1.51 | 2.22 | WINDOW | 0 | E01 | 3.0 | Fenster | MainObject | SmartPartCompressed | 100 | 7.2 | 3.75 |  |  | Window | 1166Rau0000042125 | 1163Mak0814705965 | St | Fenstermakro, -SmartPart | 2.8496 | 0 | 70 | 70 | 70 | 70 | AllplanAttributes (Fenster) - Gewerk: Zimmer- und Holzbauarbeiten; Selbstschließend: no; ash T_Zulage Schachttür: no; ash T_Dichtschließend: no; ash T_Feststellanlage (FSA): -; ash T_nicht abschließbar: no; ash T_Schallschutz: -; Pset_WindowCommon - SmokeStop: yes
Fenster | H2 Ebene +1 | 1.5 | 1.4619 | WINDOW | 0 | E01 | 3.0 | Fenster | MainObject | SmartPartCompressed | 100 | 7.2 | 3.75 |  |  | Window | 1166Rau0000042125 | 1163Mak0814705967 | St | Fenstermakro, -SmartPart | 1.79778 | 0 | 70 | 70 | 70 | 70 | EI 30 | AllplanAttributes (Fenster) - Gewerk: Zimmer- und Holzbauarbeiten; Selbstschließend: no; ash T_Zulage Schachttür: no; ash T_Dichtschließend: no; ash T_Feststellanlage (FSA): -; ash T_nicht abschließbar: no; ash T_Schallschutz: -; Pset_WindowCommon - SmokeStop: yes
Fenster | H2 Ebene +1 | 1.75 | 4.6076 | WINDOW | 0 | E01 | 3.0 | Fenster | MainObject | SmartPartCompressed | 100 | 7.2 | 3.75 |  |  | Window | 1166Rau0000042125 | 1163Mak0814705969 | St | Fenstermakro, -SmartPart | 7.19284 | 0 | 70 | 70 | 70 | 70 | EI 30 |  |  |  |  | D5 | AllplanAttributes (Fenster) - ash D_Plannummer: 1684; Gewerk: Zimmer- und Holzbauarbeiten; Selbstschließend: no; ash T_Zulage Schachttür: no; ash T_Dichtschließend: no; ash T_Feststellanlage (FSA): -; ash T_nicht abschließbar: no; ash T_Schallschutz: -; Pset_WindowCommon - SmokeStop: yes
Fenster | H2 Ebene +1 | 1.5 | 1.4725 | WINDOW | 0 | E01 | 3.0 | Fenster | MainObject | SmartPartCompressed | 100 | 7.2 | 3.75 |  |  | Window | 1166Rau0000042125 | 1163Mak0814705955 | St | Fenstermakro, -SmartPart | 1.8122 | 0 | 70 | 70 | 70 | 70 | EI 30 | AllplanAttributes (Fenster) - Gewerk: Zimmer- und Holzbauarbeiten; Selbstschließend: no; ash T_Zulage Schachttür: no; ash T_Dichtschließend: no; ash T_Feststellanlage (FSA): -; ash T_nicht abschließbar: no; ash T_Schallschutz: -; Pset_WindowCommon - SmokeStop: yes
Fenster | H2 Ebene +1 | 1.88 | 0.64994 | WINDOW | 0 | E01 | 3.0 | Fenster | MainObject | SmartPartCompressed | 100 | 7.2 | 3.75 |  |  | Window | 1166Rau0000042125 | 1163Mak0814112850 | St | Fenstermakro, -SmartPart | 1.22189 | 0 | 0 | 0 | 0 | 0 | EI 30 | AllplanAttributes (Fenster) - Gewerk: Zimmer- und Holzbauarbeiten; Selbstschließend: no; ash T_Zulage Schachttür: no; ash T_Dichtschließend: no; ash T_Feststellanlage (FSA): -; ash T_nicht abschließbar: yes; ash T_Schallschutz: 24 dB; Positionsnummer_Text: U100; Pset_WindowCommon - SmokeStop: yes
Fenster | H2 Ebene +1 | 2.75 | 2.599 | WINDOW | 0 | E01 | 3.0 | Fenster | MainObject | SmartPartCompressed | 100 | 7.2 | 3.75 |  |  | Window | 1165Rau0000067051 | 1163Mak0813652963 | St | Fenstermakro, -SmartPart | 6.02433 | 0 | 200 | 80 | 80 | 80 | EI2 60 | AllplanAttributes (Fenster) - Gewerk: Zimmer- und Holzbauarbeiten; Selbstschließend: no; ash T_Zulage Schachttür: no; ash T_Dichtschließend: no; ash T_Feststellanlage (FSA): -; ash T_nicht abschließbar: yes; ash T_Schallschutz: -; Positionsnummer_Text: U100; Pset_WindowCommon - SmokeStop: no
Fenster | H2 Ebene +1 | 2.75 | 2.569 | WINDOW | 0 | E01 | 3.0 | Fenster | MainObject | SmartPartCompressed | 100 | 7.2 | 3.75 |  |  | Window | 1165Rau0000067051 | 1163Mak0813652961 | St | Fenstermakro, -SmartPart | 5.95023 | 0 | 200 | 80 | 80 | 80 | EI2 60 | AllplanAttributes (Fenster) - Gewerk: Zimmer- und Holzbauarbeiten; Selbstschließend: no; ash T_Zulage Schachttür: no; ash T_Dichtschließend: no; ash T_Feststellanlage (FSA): -; ash T_nicht abschließbar: yes; ash T_Schallschutz: -; Positionsnummer_Text: U100; Pset_WindowCommon - SmokeStop: no
Symbol BD | H2 Ebene +1 | 3.03 | 2.45 | SKYLIGHT |  |  |  |  |  |  |  |  |  |  |  |  |  |  |  |  |  |  |  |  |  |  | 0 | 0.9 | 32 | - | AllplanAttributes (Symbol BD) - V6: 0 m; V7: 0 m; V8: 0 m; V9: 0; Programmversion: 3.0; Objektname: Bodendurchbruchsmakro; Bezeichnung: Symbol BD; Plugin_Bezeichnung: MainObject; Plugin_Objektname: SmartPartCompressed; Version: 1.0; Sonnenschutztyp: Movable; g-Wert: 0,51; Attributset-Objekt: Opening; Allright_Bauteil_ID: 1164Mak0000012692; Abrechnungsart: St
Symbol BD | H2 Ebene +1 | 3.03 | 2.45 | SKYLIGHT |  |  |  |  |  |  |  |  |  |  |  |  |  |  |  |  |  |  |  |  |  |  | 0 | 0.9 | 32 | - | AllplanAttributes (Symbol BD) - V6: 0 m; V7: 0 m; V8: 0 m; V9: 0; Programmversion: 3.0; Objektname: Bodendurchbruchsmakro; Bezeichnung: Symbol BD; Plugin_Bezeichnung: MainObject; Plugin_Objektname: SmartPartCompressed; Version: 1.0; Sonnenschutztyp: Movable; g-Wert: 0,51; Attributset-Objekt: Opening; Allright_Bauteil_ID: 1164Mak0000012683; Abrechnungsart: St
Symbol BD | H2 Ebene +1 | 0.68101 | 1.5 | SKYLIGHT |  |  |  |  |  |  |  |  |  |  |  |  |  |  |  |  |  |  |  |  |  |  | 0 | 0.9 | 32 | - | AllplanAttributes (Symbol BD) - V6: 0 m; V7: 0 m; V8: 0 m; V9: 0; Programmversion: 3.0; Objektname: Bodendurchbruchsmakro; Bezeichnung: Symbol BD; Plugin_Bezeichnung: MainObject; Plugin_Objektname: SmartPartCompressed; Version: 1.0; Sonnenschutztyp: Movable; g-Wert: 0,51; Attributset-Objekt: Opening; Allright_Bauteil_ID: 1164Mak0000004099; Abrechnungsart: St
Symbol BD | H2 Ebene +1 | 0.611 | 3.8 | SKYLIGHT |  |  |  |  |  |  |  |  |  |  |  |  |  |  |  |  |  |  |  |  |  |  | 0 | 0.9 | 32 | - | AllplanAttributes (Symbol BD) - V6: 0 m; V7: 0 m; V8: 0 m; V9: 0; Programmversion: 3.0; Objektname: Bodendurchbruchsmakro; Bezeichnung: Symbol BD; Plugin_Bezeichnung: MainObject; Plugin_Objektname: SmartPartCompressed; Version: 1.0; Sonnenschutztyp: Movable; g-Wert: 0,51; Attributset-Objekt: Opening; Allright_Bauteil_ID: 1164Mak0000004089; Abrechnungsart: St
Symbol BD | H2 Ebene +1 | 1.1275 | 3 | SKYLIGHT |  |  |  |  |  |  |  |  |  |  |  |  |  |  |  |  |  |  |  |  |  |  | 0 | 0.9 | 32 | - | AllplanAttributes (Symbol BD) - V6: 0 m; V7: 0 m; V8: 0 m; V9: 0; Programmversion: 3.0; Objektname: Bodendurchbruchsmakro; Bezeichnung: Symbol BD; Plugin_Bezeichnung: MainObject; Plugin_Objektname: SmartPartCompressed; Version: 1.0; Sonnenschutztyp: Movable; g-Wert: 0,51; Attributset-Objekt: Opening; Allright_Bauteil_ID: 1164Mak0000004106; Abrechnungsart: St
Symbol BD | H2 Ebene +1 | 1.1275 | 3 | SKYLIGHT |  |  |  |  |  |  |  |  |  |  |  |  |  |  |  |  |  |  |  |  |  |  | 0 | 0.9 | 32 | - | AllplanAttributes (Symbol BD) - V6: 0 m; V7: 0 m; V8: 0 m; V9: 0; Programmversion: 3.0; Objektname: Bodendurchbruchsmakro; Bezeichnung: Symbol BD; Plugin_Bezeichnung: MainObject; Plugin_Objektname: SmartPartCompressed; Version: 1.0; Sonnenschutztyp: Movable; g-Wert: 0,51; Attributset-Objekt: Opening; Allright_Bauteil_ID: 1164Mak0000004103; Abrechnungsart: St
Symbol BD | H2 Ebene +1 | 0.6875 | 1.50001 | SKYLIGHT |  |  |  |  |  |  |  |  |  |  |  |  |  |  |  |  |  |  |  |  |  |  | 0 | 0.9 | 32 | - | AllplanAttributes (Symbol BD) - V6: 0 m; V7: 0 m; V8: 0 m; V9: 0; Programmversion: 3.0; Objektname: Bodendurchbruchsmakro; Bezeichnung: Symbol BD; Plugin_Bezeichnung: MainObject; Plugin_Objektname: SmartPartCompressed; Version: 1.0; Sonnenschutztyp: Movable; g-Wert: 0,51; Attributset-Objekt: Opening; Allright_Bauteil_ID: 1164Mak0000004085; Abrechnungsart: St
Symbol BD | H2 Ebene +1 | 0.48 | 1.38 | SKYLIGHT |  |  |  |  |  |  |  |  |  |  |  |  |  |  |  |  |  |  |  |  |  |  | 0 | 0.9 | 32 | - | AllplanAttributes (Symbol BD) - V6: 0 m; V7: 0 m; V8: 0 m; V9: 0; Programmversion: 3.0; Objektname: Bodendurchbruchsmakro; Bezeichnung: Symbol BD; Plugin_Bezeichnung: MainObject; Plugin_Objektname: SmartPartCompressed; Version: 1.0; Sonnenschutztyp: Movable; g-Wert: 0,51; Attributset-Objekt: Opening; Allright_Bauteil_ID: 1164Mak0000007360; Abrechnungsart: St
Symbol BD | H2 Ebene +1 | 0.48 | 1.32 | SKYLIGHT |  |  |  |  |  |  |  |  |  |  |  |  |  |  |  |  |  |  |  |  |  |  | 0 | 0.9 | 32 | - | AllplanAttributes (Symbol BD) - V6: 0 m; V7: 0 m; V8: 0 m; V9: 0; Programmversion: 3.0; Objektname: Bodendurchbruchsmakro; Bezeichnung: Symbol BD; Plugin_Bezeichnung: MainObject; Plugin_Objektname: SmartPartCompressed; Version: 1.0; Sonnenschutztyp: Movable; g-Wert: 0,51; Attributset-Objekt: Opening; Allright_Bauteil_ID: 1164Mak0000007400; Abrechnungsart: St
Symbol BD | H2 Ebene +1 | 0.683 | 1.50001 | SKYLIGHT |  |  |  |  |  |  |  |  |  |  |  |  |  |  |  |  |  |  |  |  |  |  | 0 | 0.9 | 32 | - | AllplanAttributes (Symbol BD) - V6: 0 m; V7: 0 m; V8: 0 m; V9: 0; Programmversion: 3.0; Objektname: Bodendurchbruchsmakro; Bezeichnung: Symbol BD; Plugin_Bezeichnung: MainObject; Plugin_Objektname: SmartPartCompressed; Version: 1.0; Sonnenschutztyp: Movable; g-Wert: 0,51; Attributset-Objekt: Opening; Allright_Bauteil_ID: 1164Mak0000004096; Abrechnungsart: St
Symbol BD | H2 Ebene +1 | 0.51102 | 1.65 | SKYLIGHT |  |  |  |  |  |  |  |  |  |  |  |  |  |  |  |  |  |  |  |  |  |  | 0 | 0.9 | 32 | - | AllplanAttributes (Symbol BD) - V6: 0 m; V7: 0 m; V8: 0 m; V9: 0; Programmversion: 3.0; Objektname: Bodendurchbruchsmakro; Bezeichnung: Symbol BD; Plugin_Bezeichnung: MainObject; Plugin_Objektname: SmartPartCompressed; Version: 1.0; Sonnenschutztyp: Movable; g-Wert: 0,51; Attributset-Objekt: Opening; Allright_Bauteil_ID: 1164Mak0000004093; Abrechnungsart: St
Symbol BD | H2 Ebene +1 | 0.68102 | 1.5 | SKYLIGHT |  |  |  |  |  |  |  |  |  |  |  |  |  |  |  |  |  |  |  |  |  |  | 0 | 0.9 | 32 | - | AllplanAttributes (Symbol BD) - V6: 0 m; V7: 0 m; V8: 0 m; V9: 0; Programmversion: 3.0; Objektname: Bodendurchbruchsmakro; Bezeichnung: Symbol BD; Plugin_Bezeichnung: MainObject; Plugin_Objektname: SmartPartCompressed; Version: 1.0; Sonnenschutztyp: Movable; g-Wert: 0,51; Attributset-Objekt: Opening; Allright_Bauteil_ID: 1164Mak0000004081; Abrechnungsart: St
Fenster | H2 Ebene 0 | 2.5 | 2.28 | WINDOW | 0 | E00 | 3.0 | Fenster | MainObject | SmartPartCompressed | 100 | 6.1 | 0 | FA-1FL-D-1S-X-E00-040 | 0,35 | Window | 1115Rau0000005223 | 1105Mak0000061499 | St | Fenstermakro, -SmartPart | 4.56003 | 0 | 70 | 70 | 70 | 70 | 0 | 0.9 | 32 | RC 2 | F_Typ38 | AllplanAttributes (Fenster) - Gewerk: Fensterarbeiten; Positionsnummer_Text: U23; Pset_WindowCommon - Status: NEW; IsExternal: yes
Fenster | H2 Ebene 0 | 2.5 | 2.5 | WINDOW | 0 | E00 | 3.0 | Fenster | MainObject | SmartPartCompressed | 100 | 6.1 | 0 | FA-1FR-D-1S-X-E00-057 | 0,51 | Window | 1116Rau0000066291 | 1105Mak0000041040 | St | Fenstermakro, -SmartPart | 4.9494 | 0 | 70 | 70 | 70 | 70 | 0 | 0.9 | 42 | RC 2 | F_Typ2 | AllplanAttributes (Fenster) - Gewerk: Fensterarbeiten; Positionsnummer_Text: U23; Pset_WindowCommon - Status: NEW; IsExternal: yes
Fenster | H2 Ebene 0 | 2.5 | 2.5 | WINDOW | 0 | E00 | 3.0 | Fenster | MainObject | SmartPartCompressed | 100 | 6.1 | 0 | FA-1FL-D-1S-X-E00-058 | 0,51 | Window | 1116Rau0000066288 | 1105Mak0000041208 | St | Fenstermakro, -SmartPart | 4.9494 | 0 | 70 | 70 | 70 | 70 | 0 | 0.9 | 42 | RC 2 | F_Typ1 | Typ 1 | AllplanAttributes (Fenster) - ash D_Plannummer: D1726; Gewerk: Fensterarbeiten; Positionsnummer_Text: U23; Pset_WindowCommon - Status: NEW; IsExternal: yes
Fenster | H2 Ebene 0 | 2.5 | 2.5 | WINDOW | 0 | E00 | 3.0 | Fenster | MainObject | SmartPartCompressed | 100 | 6.1 | 0 | FA-1FR-D-1S-X-E00-044 | 0,51 | Window | 1116Rau0000066339 | 1105Mak0000043745 | St | Fenstermakro, -SmartPart | 4.9494 | 0 | 70 | 70 | 70 | 70 | 0 | 0.9 | 35 | RC 2 | F_Typ2 | AllplanAttributes (Fenster) - Gewerk: Fensterarbeiten; Positionsnummer_Text: U23; Pset_WindowCommon - Status: NEW; IsExternal: yes
Fenster | H2 Ebene 0 | 2.5 | 2.5 | WINDOW | 0 | E00 | 3.0 | Fenster | MainObject | SmartPartCompressed | 100 | 6.1 | 0 | FA-1FL-D-1S-X-E00-045 | 0,51 | Window | 1116Rau0000066330 | 1105Mak0000043871 | St | Fenstermakro, -SmartPart | 4.9494 | 0 | 70 | 70 | 70 | 70 | 0 | 0.9 | 35 | RC 2 | F_Typ1 | Typ 1 | AllplanAttributes (Fenster) - ash D_Plannummer: D1726; Gewerk: Fensterarbeiten; Positionsnummer_Text: U23; Pset_WindowCommon - Status: NEW; IsExternal: yes
Fenster | H2 Ebene 0 | 2.12 | 0.725 | WINDOW | 0 | E00 | 3.0 | Fenster | MainObject | SmartPartCompressed | 100 | 6.1 | 0 | FA-F-E00-L041 | 0,35 | Window | 1116Rau0000066828 | 1105Mak0000057104 | St | Fenstermakro, -SmartPart | 1.0998 | 0 | 70 | 70 | 70 | 70 | 0 | 0.9 | 32 | - | F_Typ6 | AllplanAttributes (Fenster) - Gewerk: Fensterarbeiten; Positionsnummer_Text: U23; Pset_WindowCommon - Status: NEW; IsExternal: yes
Fenster | H2 Ebene 0 | 2.12 | 1.35 | WINDOW | 0 | E00 | 3.0 | Fenster | MainObject | SmartPartCompressed | 100 | 6.1 | 0 | FA-1FR-D-1S-E00-L042 | 0,35 | Window | 1116Rau0000066366 | 1105Mak0000057146 | St | Fenstermakro, -SmartPart | 2.0002 | 0 | 70 | 70 | 70 | 70 | 0 | 0.9 | 32 | - | F_Typ4A | AllplanAttributes (Fenster) - Gewerk: Fensterarbeiten; Positionsnummer_Text: U23; Pset_WindowCommon - Status: NEW; IsExternal: yes
Fenster | H2 Ebene 0 | 2.12 | 1.35 | WINDOW | 0 | E00 | 3.0 | Fenster | MainObject | SmartPartCompressed | 100 | 6.1 | 0 | FA-1FR-D-1S-E00-L043 | 0,35 | Window | 1116Rau0000066366 | 1105Mak0000057188 | St | Fenstermakro, -SmartPart | 2.0002 | 0 | 70 | 70 | 70 | 70 | 0 | 0.9 | 32 | - | F_Typ4A | AllplanAttributes (Fenster) - Gewerk: Fensterarbeiten; Positionsnummer_Text: U23; Pset_WindowCommon - Status: NEW; IsExternal: yes
Fenster | H2 Ebene 0 | 2.12 | 1.35 | WINDOW | 0 | E00 | 3.0 | Fenster | MainObject | SmartPartCompressed | 100 | 6.1 | 0 | FA-1FR-D-1S-E00-L045 | 0,35 | Window | 1116Rau0000066366 | 1105Mak0000057272 | St | Fenstermakro, -SmartPart | 2.0002 | 0 | 70 | 70 | 70 | 70 | 0 | 0.9 | 32 | - | F_Typ4A | AllplanAttributes (Fenster) - Gewerk: Fensterarbeiten; Positionsnummer_Text: U23; Pset_WindowCommon - Status: NEW; IsExternal: yes
Fenster | H2 Ebene 0 | 2.12 | 1.35 | WINDOW | 0 | E00 | 3.0 | Fenster | MainObject | SmartPartCompressed | 100 | 6.1 | 0 | FA-1FR-D-1S-E00-L046 | 0,35 | Window | 1116Rau0000066366 | 1105Mak0000085794 | St | Fenstermakro, -SmartPart | 2.0002 | 0 | 70 | 70 | 70 | 70 | 0 | 0.9 | 32 | - | F_Typ4A | AllplanAttributes (Fenster) - Gewerk: Fensterarbeiten; Positionsnummer_Text: U23; Pset_WindowCommon - Status: NEW; IsExternal: yes
Fenster | H2 Ebene 0 | 2.12 | 0.725 | WINDOW | 0 | E00 | 3.0 | Fenster | MainObject | SmartPartCompressed | 100 | 6.1 | 0 | FA-F-E00-L044 | 0,35 | Window | 1116Rau0000065738 | 1105Mak0000057230 | St | Fenstermakro, -SmartPart | 1.0998 | 0 | 70 | 70 | 70 | 70 | 0 | 0.9 | 32 | - | F_Typ6 | AllplanAttributes (Fenster) - Gewerk: Fensterarbeiten; Positionsnummer_Text: U23; Pset_WindowCommon - Status: NEW; IsExternal: yes
Fenster | H2 Ebene 0 | 2.12 | 1.35 | WINDOW | 0 | E00 | 3.0 | Fenster | MainObject | SmartPartCompressed | 100 | 6.1 | 0 | FA-1FL-D-1S-E00-L033 | 0,35 | Window | 1116Rau0000066366 | 1105Mak2005793028 | St | Fenstermakro, -SmartPart | 2.0002 | 0 | 70 | 70 | 70 | 70 | 0 | 0.9 | 32 | - | F_Typ3A | AllplanAttributes (Fenster) - Gewerk: Fensterarbeiten; Positionsnummer_Text: U23; Pset_WindowCommon - Status: NEW; IsExternal: yes
Fenster | H2 Ebene 0 | 2.12 | 1.35 | WINDOW | 0 | E00 | 3.0 | Fenster | MainObject | SmartPartCompressed | 100 | 6.1 | 0 | FA-1FL-D-1S-E00-L034 | 0,35 | Window | 1116Rau0000066366 | 1105Mak2005793130 | St | Fenstermakro, -SmartPart | 2.0002 | 0 | 70 | 70 | 70 | 70 | 0 | 0.9 | 32 | - | F_Typ3A | Typ 3 | AllplanAttributes (Fenster) - ash D_Plannummer: D1727; Gewerk: Fensterarbeiten; Positionsnummer_Text: U23; Pset_WindowCommon - Status: NEW; IsExternal: yes
Fenster | H2 Ebene 0 | 2.12 | 1.35 | WINDOW | 0 | E00 | 3.0 | Fenster | MainObject | SmartPartCompressed | 100 | 6.1 | 0 | FA-1FL-D-1S-E00-L037 | 0,35 | Window | 1116Rau0000066366 | 1105Mak2005793224 | St | Fenstermakro, -SmartPart | 2.0002 | 0 | 70 | 70 | 70 | 70 | 0 | 0.9 | 32 | - | F_Typ3A | Typ 3 | AllplanAttributes (Fenster) - ash D_Plannummer: D1727; Gewerk: Fensterarbeiten; Positionsnummer_Text: U23; Pset_WindowCommon - Status: NEW; IsExternal: yes
Fenster | H2 Ebene 0 | 2.12 | 1.35 | WINDOW | 0 | E00 | 3.0 | Fenster | MainObject | SmartPartCompressed | 100 | 6.1 | 0 | FA-1FL-D-1S-E00-L038 | 0,35 | Window | 1116Rau0000066366 | 1105Mak2005793306 | St | Fenstermakro, -SmartPart | 2.0002 | 0 | 70 | 70 | 70 | 70 | 0 | 0.9 | 32 | - | F_Typ3A | Typ 3 | AllplanAttributes (Fenster) - ash D_Plannummer: D1727; Gewerk: Fensterarbeiten; Positionsnummer_Text: U23; Pset_WindowCommon - Status: NEW; IsExternal: yes
Fenster | H2 Ebene 0 | 2.12 | 1.35 | WINDOW | 0 | E00 | 3.0 | Fenster | MainObject | SmartPartCompressed | 100 | 6.1 | 0 | FA-1FL-D-1S-E00-L039 | 0,35 | Window | 1116Rau0000066366 | 1105Mak2005793400 | St | Fenstermakro, -SmartPart | 2.0002 | 0 | 70 | 70 | 70 | 70 | 0 | 0.9 | 32 | - | F_Typ3A | Typ 3 | AllplanAttributes (Fenster) - ash D_Plannummer: D1727; Gewerk: Fensterarbeiten; Positionsnummer_Text: U23; Pset_WindowCommon - Status: NEW; IsExternal: yes
Fenster | H2 Ebene 0 | 2.12 | 1.35 | WINDOW | 0 | E00 | 3.0 | Fenster | MainObject | SmartPartCompressed | 100 | 6.1 | 0 | FA-1FL-D-1S-E00-L024 | 0,35 | Window | 1116Rau0000066366 | 1105Mak0000053645 | St | Fenstermakro, -SmartPart | 2.0002 | 0 | 70 | 70 | 70 | 70 | 0 | 0.9 | 32 | - | F_Typ3A | Typ 3 | AllplanAttributes (Fenster) - ash D_Plannummer: D1727; Gewerk: Fensterarbeiten; Positionsnummer_Text: U23; Pset_WindowCommon - Status: NEW; IsExternal: yes
Fenster | H2 Ebene 0 | 2.12 | 1.35 | WINDOW | 0 | E00 | 3.0 | Fenster | MainObject | SmartPartCompressed | 100 | 6.1 | 0 | FA-1FL-D-1S-E00-L023 | 0,35 | Window | 1116Rau0000066366 | 1105Mak0000053687 | St | Fenstermakro, -SmartPart | 2.0002 | 0 | 70 | 70 | 70 | 70 | 0 | 0.9 | 32 | - | F_Typ3A | Typ 3 | AllplanAttributes (Fenster) - ash D_Plannummer: D1727; Gewerk: Fensterarbeiten; Positionsnummer_Text: U23; Pset_WindowCommon - Status: NEW; IsExternal: yes
Fenster | H2 Ebene 0 | 2.12 | 1.35 | WINDOW | 0 | E00 | 3.0 | Fenster | MainObject | SmartPartCompressed | 100 | 6.1 | 0 | FA-1FR-D-1S-E00-L030 | 0,35 | Window | 1116Rau0000066366 | 1105Mak2005780530 | St | Fenstermakro, -SmartPart | 2.0002 | 0 | 70 | 70 | 70 | 70 | 0 | 0.9 | 32 | - | F_Typ4A | AllplanAttributes (Fenster) - Gewerk: Fensterarbeiten; Positionsnummer_Text: U23; Pset_WindowCommon - Status: NEW; IsExternal: yes
Fenster | H2 Ebene 0 | 2.12 | 1.35 | WINDOW | 0 | E00 | 3.0 | Fenster | MainObject | SmartPartCompressed | 100 | 6.1 | 0 | FA-1FR-D-1S-E00-L007 | 0,35 | Window | 1116Rau0000066366 | 1105Mak0000051368 | St | Fenstermakro, -SmartPart | 2.0002 | 0 | 70 | 70 | 70 | 70 | 0 | 0.9 | 32 | - | F_Typ4A | Typ 4 | AllplanAttributes (Fenster) - ash D_Plannummer: D1727; Gewerk: Fensterarbeiten; Positionsnummer_Text: U23; Pset_WindowCommon - Status: NEW; IsExternal: yes
Fenster | H2 Ebene 0 | 2.12 | 0.725 | WINDOW | 0 | E00 | 3.0 | Fenster | MainObject | SmartPartCompressed | 100 | 6.1 | 0 | FA-F-E00-L003 | 0,35 | Window | 1116Rau0000065738 | 1105Mak0000051613 | St | Fenstermakro, -SmartPart | 1.0998 | 0 | 70 | 70 | 70 | 70 | 0 | 0.9 | 32 | - | F_Typ6 | AllplanAttributes (Fenster) - Gewerk: Fensterarbeiten; Positionsnummer_Text: U23; Pset_WindowCommon - Status: NEW; IsExternal: yes
Fenster | H2 Ebene 0 | 2.12 | 1.35 | WINDOW | 0 | E00 | 3.0 | Fenster | MainObject | SmartPartCompressed | 100 | 6.1 | 0 | FA-1FR-D-1S-E00-L002 | 0,35 | Window | 1116Rau0000066366 | 1105Mak0000085359 | St | Fenstermakro, -SmartPart | 2.0002 | 0 | 70 | 70 | 70 | 70 | 0 | 0.9 | 32 | - | F_Typ4A | AllplanAttributes (Fenster) - Gewerk: Fensterarbeiten; Positionsnummer_Text: U23; Pset_WindowCommon - Status: NEW; IsExternal: yes
Fenster | H2 Ebene 0 | 2.15 | 1.35 | WINDOW | 0 | E00 | 3.0 | Fenster | MainObject | SmartPartCompressed | 100 | 6.1 | 0 | FA-1FR-D-1S-E00-L004 | 0,35 | Window | 1116Rau0000066366 | 1105Mak0000051498 | St | Fenstermakro, -SmartPart | 2.0314 | 0 | 70 | 70 | 70 | 70 | 0 | 0.9 | 32 | - | F_Typ4A | Typ 4 | AllplanAttributes (Fenster) - ash D_Plannummer: D1727; Gewerk: Fensterarbeiten; Positionsnummer_Text: U23; Pset_WindowCommon - Status: NEW; IsExternal: yes
Fenster | H2 Ebene 0 | 2.12 | 0.725 | WINDOW | 0 | E00 | 3.0 | Fenster | MainObject | SmartPartCompressed | 100 | 6.1 | 0 | FA-F-E00-L008 | 0,35 | Window | 1116Rau0000066414 | 1105Mak0000051295 | St | Fenstermakro, -SmartPart | 1.0998 | 0 | 70 | 70 | 70 | 70 | 0 | 0.9 | 32 | - | F_Typ6 | AllplanAttributes (Fenster) - Gewerk: Fensterarbeiten; Positionsnummer_Text: U23; Pset_WindowCommon - Status: NEW; IsExternal: yes
Fenster | H2 Ebene 0 | 2.12 | 1.35 | WINDOW | 0 | E00 | 3.0 | Fenster | MainObject | SmartPartCompressed | 100 | 6.1 | 0 | FA-1FR-D-1S-E00-L005 | 0,35 | Window | 1116Rau0000066366 | 1105Mak0000051456 | St | Fenstermakro, -SmartPart | 2.0002 | 0 | 70 | 70 | 70 | 70 | 0 | 0.9 | 32 | - | F_Typ4A | Typ 4 | AllplanAttributes (Fenster) - ash D_Plannummer: D1727; Gewerk: Fensterarbeiten; Positionsnummer_Text: U23; Pset_WindowCommon - Status: NEW; IsExternal: yes
Fenster | H2 Ebene 0 | 2.12 | 1.35 | WINDOW | 0 | E00 | 3.0 | Fenster | MainObject | SmartPartCompressed | 100 | 6.1 | 0 | FA-1FL-D-1S-E00-L028 | 0,35 | Window | 1116Rau0000066366 | 1105Mak2005780334 | St | Fenstermakro, -SmartPart | 2.0002 | 0 | 70 | 70 | 70 | 70 | 0 | 0.9 | 32 | - | F_Typ3A | Typ 3 | AllplanAttributes (Fenster) - ash D_Plannummer: D1727; Gewerk: Fensterarbeiten; Positionsnummer_Text: U23; Pset_WindowCommon - Status: NEW; IsExternal: yes
Fenster | H2 Ebene 0 | 2.12 | 1.35 | WINDOW | 0 | E00 | 3.0 | Fenster | MainObject | SmartPartCompressed | 100 | 6.1 | 0 | FA-1FL-D-1S-E00-L029 | 0,35 | Window | 1116Rau0000066366 | 1105Mak2005780416 | St | Fenstermakro, -SmartPart | 2.0002 | 0 | 70 | 70 | 70 | 70 | 0 | 0.9 | 32 | - | F_Typ3A | Typ 3 | AllplanAttributes (Fenster) - ash D_Plannummer: D1727; Gewerk: Fensterarbeiten; Positionsnummer_Text: U23; Pset_WindowCommon - Status: NEW; IsExternal: yes
Fenster | H2 Ebene 0 | 2.12 | 1.35 | WINDOW | 0 | E00 | 3.0 | Fenster | MainObject | SmartPartCompressed | 100 | 6.1 | 0 | FA-1FL-D-1S-E00-L025 | 0,35 | Window | 1116Rau0000066366 | 1105Mak0000053264 | St | Fenstermakro, -SmartPart | 2.0002 | 0 | 70 | 70 | 70 | 70 | 0 | 0.9 | 32 | - | F_Typ3A | Typ 3 | AllplanAttributes (Fenster) - ash D_Plannummer: D1727; Gewerk: Fensterarbeiten; Positionsnummer_Text: U23; Pset_WindowCommon - Status: NEW; IsExternal: yes
Fenster | H2 Ebene 0 | 2.12 | 1.35 | WINDOW | 0 | E00 | 3.0 | Fenster | MainObject | SmartPartCompressed | 100 | 6.1 | 0 | FA-1FL-D-1S-E00-L026 | 0,35 | Window | 1116Rau0000066366 | 1105Mak2005780224 | St | Fenstermakro, -SmartPart | 2.0002 | 0 | 70 | 70 | 70 | 70 | 0 | 0.9 | 32 | - | F_Typ3A | Typ 3 | AllplanAttributes (Fenster) - ash D_Plannummer: D1727; Gewerk: Fensterarbeiten; Positionsnummer_Text: U23; Pset_WindowCommon - Status: NEW; IsExternal: yes
Fenster | H2 Ebene 0 | 2.52 | 0.675 | WINDOW | 0 | E00 | 3.0 | Fenster | MainObject | SmartPartCompressed | 100 | 6.1 | 0 | TA-1FL-D-2S-E00-L006 | 0,35 | Window | 1116Rau0000065738 | 1105Mak2005789701 | St | Fenstermakro, -SmartPart | 1.2733 | 0 | 70 | 70 | 70 | 70 | 0 | 0.9 | 32 | RC 1 | F_Typ6 | AllplanAttributes (Fenster) - Gewerk: Fensterarbeiten; Positionsnummer_Text: U23; Pset_WindowCommon - Status: NEW; IsExternal: yes
Fenster | H2 Ebene 0 | 2.52 | 0.675 | WINDOW | 0 | E00 | 3.0 | Fenster | MainObject | SmartPartCompressed | 100 | 6.1 | 0 | TA-1FL-D-2S-E00-L006 | 0,35 | Window | 1116Rau0000065738 | 1105Mak2005789209 | St | Fenstermakro, -SmartPart | 1.2733 | 0 | 70 | 70 | 70 | 70 | 0 | 0.9 | 32 | - | F_Typ6 | AllplanAttributes (Fenster) - Gewerk: Fensterarbeiten; Positionsnummer_Text: U23; Pset_WindowCommon - Status: NEW; IsExternal: yes
Fenster | H2 Ebene 0 | 2.5 | 1.25 | WINDOW | 0 | E00 | 3.0 | Fenster | MainObject | SmartPartCompressed | 100 | 6.1 | 0 | FA-1FL-D-1S-E00-051 | 0,35 | Window | 1116Rau0000066366 | 1105Mak0811564234 | St | Fenstermakro, -SmartPart | 2.1694 | 0 | 70 | 70 | 70 | 70 | 0 | 0.9 | 32 | RC 2 | F_Typ3 | Typ 3 | AllplanAttributes (Fenster) - ash D_Plannummer: D1727; Gewerk: Fensterarbeiten; Positionsnummer_Text: U23; Pset_WindowCommon - Status: NEW; IsExternal: yes
Fenster | H2 Ebene 0 | 2.5 | 1.25 | WINDOW | 0 | E00 | 3.0 | Fenster | MainObject | SmartPartCompressed | 100 | 6.1 | 0 | FA-1FL-D-1S-E00-050 | 0,35 | Window | 1116Rau0000066366 | 1105Mak0811564230 | St | Fenstermakro, -SmartPart | 2.1694 | 0 | 70 | 70 | 70 | 70 | 0 | 0.9 | 32 | RC 2 | F_Typ3 | Typ 3 | AllplanAttributes (Fenster) - ash D_Plannummer: D1727; Gewerk: Fensterarbeiten; Positionsnummer_Text: U23; Pset_WindowCommon - Status: NEW; IsExternal: yes
Fenster | H2 Ebene 0 | 2.12 | 1.35 | WINDOW | 0 | E00 | 3.0 | Fenster | MainObject | SmartPartCompressed | 100 | 6.1 | 0 | FA-1FR-D-1S-E00-L006a | 0,35 | Window | 1116Rau0000066366 | 1105Mak2005779355 | St | Fenstermakro, -SmartPart | 2.0002 | 0 | 70 | 70 | 70 | 70 | 0 | 0.9 | 32 | - | F_Typ4A | Typ 4 | AllplanAttributes (Fenster) - ash D_Plannummer: D1727; Gewerk: Fensterarbeiten; Positionsnummer_Text: U23; Pset_WindowCommon - Status: NEW; IsExternal: yes
Fenster | H2 Ebene 0 | 2.12 | 1.35 | WINDOW | 0 | E00 | 3.0 | Fenster | MainObject | SmartPartCompressed | 100 | 6.1 | 0 | FA-1FR-D-1S-E00-L006b | 0,35 | Window | 1116Rau0000066366 | 1105Mak2005779437 | St | Fenstermakro, -SmartPart | 2.0002 | 0 | 70 | 70 | 70 | 70 | 0 | 0.9 | 32 | - | F_Typ4A | Typ 4 | AllplanAttributes (Fenster) - ash D_Plannummer: D1727; Gewerk: Fensterarbeiten; Positionsnummer_Text: U23; Pset_WindowCommon - Status: NEW; IsExternal: yes
Fenster | H2 Ebene 0 | 2.12 | 1.35 | WINDOW | 0 | E00 | 3.0 | Fenster | MainObject | SmartPartCompressed | 100 | 6.1 | 0 | FA-1FR-D-1S-E00-L006c | 0,35 | Window | 1116Rau0000066366 | 1105Mak2005779519 | St | Fenstermakro, -SmartPart | 2.0002 | 0 | 70 | 70 | 70 | 70 | 0 | 0.9 | 32 | - | F_Typ4A | Typ 3 | AllplanAttributes (Fenster) - ash D_Plannummer: D1727; Gewerk: Fensterarbeiten; Positionsnummer_Text: U23; Pset_WindowCommon - Status: NEW; IsExternal: yes
Fenster | H2 Ebene 0 | 2.12 | 1.35 | WINDOW | 0 | E00 | 3.0 | Fenster | MainObject | SmartPartCompressed | 100 | 6.1 | 0 | FA-1FL-D-1S-E00-L040a | 0,35 | Window | 1116Rau0000066366 | 1105Mak2005793524 | St | Fenstermakro, -SmartPart | 2.0002 | 0 | 70 | 70 | 70 | 70 | 0 | 0.9 | 32 | - | F_Typ3A | Typ 3 | AllplanAttributes (Fenster) - ash D_Plannummer: D1727; Gewerk: Fensterarbeiten; Positionsnummer_Text: U23; Pset_WindowCommon - Status: NEW; IsExternal: yes
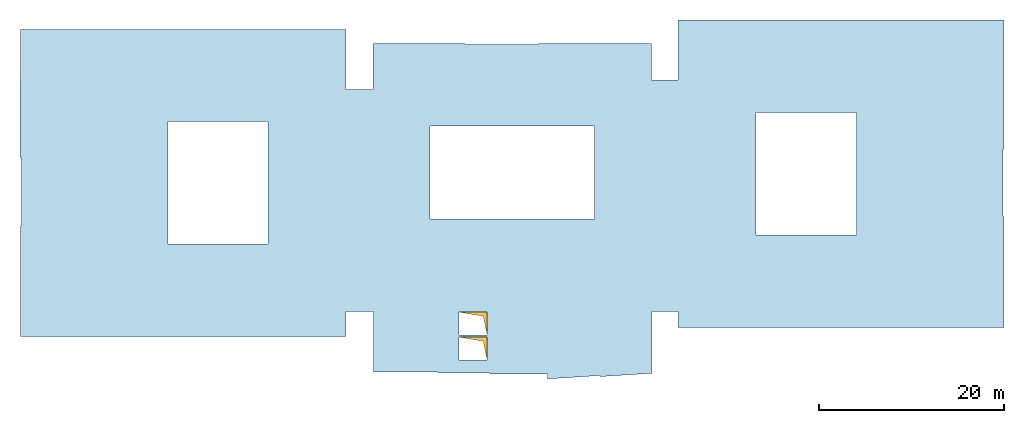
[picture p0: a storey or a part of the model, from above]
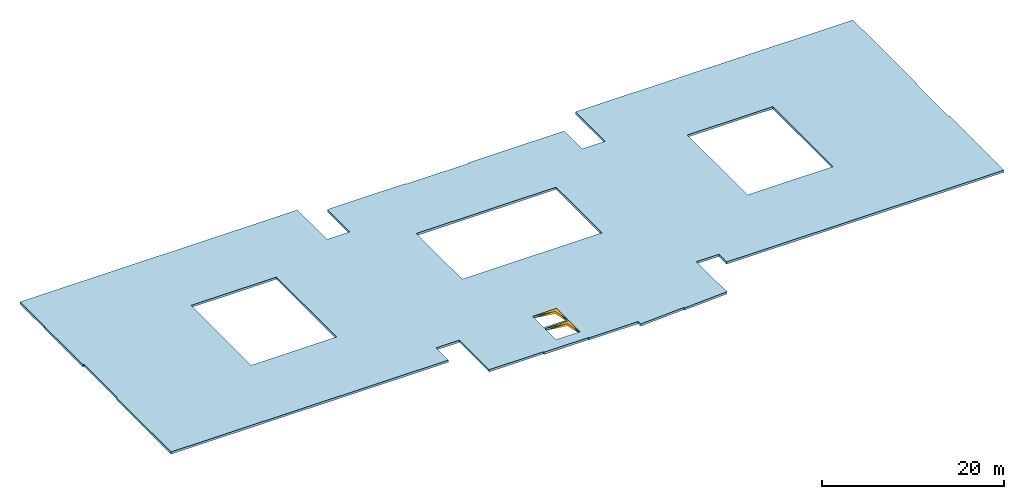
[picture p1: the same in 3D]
Properties of the parts of a building model (IFC4), part 80 of 80

# IfcWindow (393)
Name | In | OverallHeight (m) | OverallWidth (m) | PredefinedType | AllplanAttributes (Fenster), V6 (m) = AllplanAttributes (Fenster), V7 (m) = AllplanAttributes (Fenster), V8 (m) = AllplanAttributes (Fenster), V9 = HeightWindowSillOutside = HeightWindowSillInside | AllplanAttributes (Fenster), Ortscode_Geschoßbezeichnung | AllplanAttributes (Fenster), Programmversion | AllplanAttributes (Fenster), Bezeichnung | AllplanAttributes (Fenster), Plugin_Bezeichnung | AllplanAttributes (Fenster), Plugin_Objektname | AllplanAttributes (Fenster), Glasanteil_berücksichtigen | AllplanAttributes (Fenster), Version | AllplanAttributes (Fenster), OKFF | ash T_Tür-Nr. | AllplanAttributes (Fenster), g-Wert | AllplanAttributes (Fenster), Attributset-Objekt | AllplanAttributes (Fenster), P_ID | AllplanAttributes (Fenster), Allright_Bauteil_ID | AllplanAttributes (Fenster), Abrechnungsart | AllplanAttributes (Fenster), Objektname | GlassSurface | OffsetOpeningBottom = OffsetOpeningTop = OffsetOpeningLeft = OffsetOpeningRight | DeductionOpeningBottom | DeductionOpeningLeft | DeductionOpeningRight | DeductionOpeningTop | FireRating | ThermalTransmittance (W/K/m2) | AcousticRating | SecurityRating | Reference | AllplanAttributes (Fenster), ash D_Detailverweis
Fenster | H2 Ebene 0 | 2.12 | 1.35 | WINDOW | 0 | E00 | 3.0 | Fenster | MainObject | SmartPartCompressed | 100 | 6.1 | 0 | FA-1FL-D-1S-E00-L040b | 0,35 | Window | 1116Rau0000066366 | 1105Mak2005793606 | St | Fenstermakro, -SmartPart | 2.0002 | 0 | 70 | 70 | 70 | 70 | 0 | 0.9 | 32 | - | F_Typ3A | Typ 3 | AllplanAttributes (Fenster) - ash D_Plannummer: D1727; Gewerk: Fensterarbeiten; Positionsnummer_Text: U23; Pset_WindowCommon - Status: NEW; IsExternal: yes
Fenster | H2 Ebene 0 | 2.12 | 1.35 | WINDOW | 0 | E00 | 3.0 | Fenster | MainObject | SmartPartCompressed | 100 | 6.1 | 0 | FA-1FL-D-1S-E00-L040c | 0,35 | Window | 1116Rau0000066366 | 1105Mak2005793688 | St | Fenstermakro, -SmartPart | 2.0002 | 0 | 70 | 70 | 70 | 70 | 0 | 0.9 | 32 | - | F_Typ3A | Typ 3 | AllplanAttributes (Fenster) - ash D_Plannummer: D1727; Gewerk: Fensterarbeiten; Positionsnummer_Text: U23; Pset_WindowCommon - Status: NEW; IsExternal: yes
Fenster | H2 Ebene 0 | 2.12 | 1.35 | WINDOW | 0 | E00 | 3.0 | Fenster | MainObject | SmartPartCompressed | 100 | 6.1 | 0 | FA-1FR-D-1S-E00-L032a | 0,35 | Window | 1116Rau0000066366 | 1105Mak2005792575 | St | Fenstermakro, -SmartPart | 2.0002 | 0 | 70 | 70 | 70 | 70 | 0 | 0.9 | 32 | - | F_Typ4A | Typ 4 | AllplanAttributes (Fenster) - ash D_Plannummer: D1727; Gewerk: Fensterarbeiten; Positionsnummer_Text: U23; Pset_WindowCommon - Status: NEW; IsExternal: yes
Fenster | H2 Ebene 0 | 2.12 | 1.35 | WINDOW | 0 | E00 | 3.0 | Fenster | MainObject | SmartPartCompressed | 100 | 6.1 | 0 | FA-1FR-D-1S-E00-L032b | 0,35 | Window | 1116Rau0000066366 | 1105Mak2005792657 | St | Fenstermakro, -SmartPart | 2.0002 | 0 | 70 | 70 | 70 | 70 | 0 | 0.9 | 32 | - | F_Typ4A | Typ 4 | AllplanAttributes (Fenster) - ash D_Plannummer: D1727; Gewerk: Fensterarbeiten; Positionsnummer_Text: U23; Pset_WindowCommon - Status: NEW; IsExternal: yes
Fenster | H2 Ebene 0 | 2.12 | 1.35 | WINDOW | 0 | E00 | 3.0 | Fenster | MainObject | SmartPartCompressed | 100 | 6.1 | 0 | FA-1FR-D-1S-E00-L032c | 0,35 | Window | 1116Rau0000066366 | 1105Mak2005792749 | St | Fenstermakro, -SmartPart | 2.0002 | 0 | 70 | 70 | 70 | 70 | 0 | 0.9 | 32 | - | F_Typ4A | Typ 4 | AllplanAttributes (Fenster) - ash D_Plannummer: D1727; Gewerk: Fensterarbeiten; Positionsnummer_Text: U23; Pset_WindowCommon - Status: NEW; IsExternal: yes
Fenster | H2 Ebene 0 | 2.12 | 1.35 | WINDOW | 0 | E00 | 3.0 | Fenster | MainObject | SmartPartCompressed | 100 | 6.1 | 0 | FA-1FL-D-1S-E00-L022 | 0,35 | Window | 1116Rau0000066366 | 1105Mak0000053729 | St | Fenstermakro, -SmartPart | 2.0002 | 0 | 70 | 70 | 70 | 70 | 0 | 0.9 | 32 | - | F_Typ3A | Typ 3 | AllplanAttributes (Fenster) - ash D_Plannummer: D1727; Gewerk: Fensterarbeiten; Positionsnummer_Text: U23; Pset_WindowCommon - Status: NEW; IsExternal: yes
Fenster | H2 Ebene 0 | 2.5 | 2.5 | WINDOW | 0 |  | 3.0 | Fenster | MainObject | SmartPartCompressed | 100 | 6.1 |  | FA-1FR-D-1S-X-E00-011 | 0,51 |  | 1116Rau0000065759 | 1105Mak0811557412 | St | Fenstermakro, -SmartPart | 4.9494 | 0 | 70 | 70 | 70 | 70 | 0 | 0.9 | 35 | RC 2 | F_Typ2 | AllplanAttributes (Fenster) - Positionsnummer_Text: U23
Fenster | H2 Ebene 0 | 2.5 | 2.5 | WINDOW | 0 |  | 3.0 | Fenster | MainObject | SmartPartCompressed | 100 | 6.1 |  | FA-1FL-D-1S-X-E00-012 | 0,51 |  | 1116Rau0000065849 | 1105Mak0811557368 | St | Fenstermakro, -SmartPart | 4.9494 | 0 | 70 | 70 | 70 | 70 | 0 | 0.9 | 35 | RC 2 | F_Typ1 | Typ 1 | AllplanAttributes (Fenster) - ash D_Plannummer: D1726; Positionsnummer_Text: U23
Fenster | H2 Ebene 0 | 2.5 | 2.5 | WINDOW | 0 |  | 3.0 | Fenster | MainObject | SmartPartCompressed | 100 | 6.1 |  | FA-1FR-D-1S-X-E00-013 | 0,51 |  | 1116Rau0000065825 | 1105Mak0000039955 | St | Fenstermakro, -SmartPart | 4.9494 | 0 | 70 | 70 | 70 | 70 | 0 | 0.9 | 35 | RC 2 | F_Typ2 | AllplanAttributes (Fenster) - Positionsnummer_Text: U23
Fenster | H2 Ebene 0 | 2.5 | 2.5 | WINDOW | 0 |  | 3.0 | Fenster | MainObject | SmartPartCompressed | 100 | 6.1 |  | FA-1FL-D-1S-X-E00-014 | 0,51 |  | 1116Rau0000065828 | 1105Mak0000039997 | St | Fenstermakro, -SmartPart | 4.9494 | 0 | 70 | 70 | 70 | 70 | 0 | 0.9 | 35 | RC 2 | F_Typ1 | Typ 1 | AllplanAttributes (Fenster) - ash D_Plannummer: D1726; Positionsnummer_Text: U23
Fenster | H2 Ebene 0 | 2.5 | 2.5 | WINDOW | 0 |  | 3.0 | Fenster | MainObject | SmartPartCompressed | 100 | 6.1 |  | FA-1FR-D-1S-X-E00-015 | 0,51 |  | 1116Rau0000065831 | 1105Mak0000040051 | St | Fenstermakro, -SmartPart | 4.9494 | 0 | 70 | 70 | 70 | 70 | 0 | 0.9 | 35 | RC 2 | F_Typ2 | AllplanAttributes (Fenster) - Positionsnummer_Text: U23
Fenster | H2 Ebene 0 | 2.5 | 2.5 | WINDOW | 0 |  | 3.0 | Fenster | MainObject | SmartPartCompressed | 100 | 6.1 |  | FA-1FL-D-1S-X-E00-016 | 0,51 |  | 1116Rau0000065834 | 1105Mak0000040093 | St | Fenstermakro, -SmartPart | 4.9494 | 0 | 70 | 70 | 70 | 70 | 0 | 0.9 | 35 | RC 2 | F_Typ1 | Typ 1 | AllplanAttributes (Fenster) - ash D_Plannummer: D1726; Positionsnummer_Text: U23
Fenster | H2 Ebene 0 | 2.5 | 2.5 | WINDOW | 0 | E00 | 3.0 | Fenster | MainObject | SmartPartCompressed | 100 | 6.1 | 0 | FA-1FR-D-1S-X-E00-034 | 0,51 | Window | 1116Rau0000065846 | 1105Mak0000046678 | St | Fenstermakro, -SmartPart | 4.9494 | 0 | 70 | 70 | 70 | 70 | 0 | 0.9 | 32 | RC 2 | F_Typ2 | AllplanAttributes (Fenster) - Gewerk: Fensterarbeiten; Positionsnummer_Text: U23; Pset_WindowCommon - Status: NEW; IsExternal: yes
Fenster | H2 Ebene 0 | 2.5 | 2.5 | WINDOW | 0 | E00 | 3.0 | Fenster | MainObject | SmartPartCompressed | 100 | 6.1 | 0 | FA-1FL-D-1S-X-E00-035 | 0,51 | Window | 1116Rau0000065886 | 1105Mak0000046510 | St | Fenstermakro, -SmartPart | 4.9494 | 0 | 70 | 70 | 70 | 70 | 0 | 0.9 | 32 | RC 2 | F_Typ1 | Typ 1 | AllplanAttributes (Fenster) - ash D_Plannummer: D1726; Gewerk: Fensterarbeiten; Positionsnummer_Text: U23; Pset_WindowCommon - Status: NEW; IsExternal: yes
Fenster | H2 Ebene 0 | 2.5 | 2.5 | WINDOW | 0 | E00 | 3.0 | Fenster | MainObject | SmartPartCompressed | 100 | 6.1 | 0 | FA-1FL-D-1S-X-E00-037 | 0,51 | Window | 1116Rau0000065852 | 1105Mak0000046552 | St | Fenstermakro, -SmartPart | 4.9494 | 0 | 70 | 70 | 70 | 70 | 0 | 0.9 | 32 | RC 2 | F_Typ1 | Typ 1 | AllplanAttributes (Fenster) - ash D_Plannummer: D1726; Gewerk: Fensterarbeiten; Positionsnummer_Text: U23; Pset_WindowCommon - Status: NEW; IsExternal: yes
Fenster | H2 Ebene 0 | 2.5 | 2.5 | WINDOW | 0 | E00 | 3.0 | Fenster | MainObject | SmartPartCompressed | 100 | 6.1 | 0 | FA-1FR-D-1S-X-E00-036 | 0,51 | Window | 1116Rau0000065843 | 1105Mak0000046720 | St | Fenstermakro, -SmartPart | 4.9494 | 0 | 70 | 70 | 70 | 70 | 0 | 0.9 | 32 | RC 2 | F_Typ2 | AllplanAttributes (Fenster) - Gewerk: Fensterarbeiten; Positionsnummer_Text: U23; Pset_WindowCommon - Status: NEW; IsExternal: yes
Fenster | H2 Ebene 0 | 2.5 | 2.28 | WINDOW | 0 | E00 | 3.0 | Fenster | MainObject | SmartPartCompressed | 100 | 6.1 | 0 | FA-1FR-D-1S-X-E00-041 | 0,35 | Window | 1115Rau0000005201 | 1105Mak0000061274 | St | Fenstermakro, -SmartPart | 4.4522 | 0 | 70 | 70 | 70 | 70 | 0 | 0.9 | 32 | RC 2 | F_Typ7 | AllplanAttributes (Fenster) - Gewerk: Fensterarbeiten; Positionsnummer_Text: U23; Pset_WindowCommon - Status: NEW; IsExternal: yes
Fenster | H2 Ebene 0 | 2.5 | 2.5 | WINDOW | 0 | E00 | 3.0 | Fenster | MainObject | SmartPartCompressed | 100 | 6.1 | 0 | FA-1FR-D-1S-X-E00-048 | 0,51 | Window | 1116Rau0000066512 | 1105Mak0000043661 | St | Fenstermakro, -SmartPart | 4.9494 | 0 | 70 | 70 | 70 | 70 | 0 | 0.9 | 35 | RC 2 | F_Typ2 | AllplanAttributes (Fenster) - Gewerk: Fensterarbeiten; Positionsnummer_Text: U23; Pset_WindowCommon - Status: NEW; IsExternal: yes
Fenster | H2 Ebene 0 | 2.5 | 2.5 | WINDOW | 0 | E00 | 3.0 | Fenster | MainObject | SmartPartCompressed | 100 | 6.1 | 0 | FA-1FR-D-1S-X-E00-046 | 0,51 | Window | 1116Rau0000066342 | 1105Mak0000043703 | St | Fenstermakro, -SmartPart | 4.9494 | 0 | 70 | 70 | 70 | 70 | 0 | 0.9 | 35 | RC 2 | F_Typ2 | AllplanAttributes (Fenster) - Gewerk: Fensterarbeiten; Positionsnummer_Text: U23; Pset_WindowCommon - Status: NEW; IsExternal: yes
Fenster | H2 Ebene 0 | 2.5 | 2.5 | WINDOW | 0 | E00 | 3.0 | Fenster | MainObject | SmartPartCompressed | 100 | 6.1 | 0 | FA-1FL-D-1S-X-E00-047 | 0,51 | Window | 1116Rau0000066498 | 1105Mak0000043829 | St | Fenstermakro, -SmartPart | 4.9494 | 0 | 70 | 70 | 70 | 70 | 0 | 0.9 | 35 | RC 2 | F_Typ1 | Typ 1 | AllplanAttributes (Fenster) - ash D_Plannummer: D1726; Gewerk: Fensterarbeiten; Positionsnummer_Text: U23; Pset_WindowCommon - Status: NEW; IsExternal: yes
Fenster | H2 Ebene 0 | 2.5 | 2.5 | WINDOW | 0 | E00 | 3.0 | Fenster | MainObject | SmartPartCompressed | 100 | 6.1 | 0 | FA-1FL-D-1S-X-E00-043 | 0,51 | Window | 1116Rau0000066336 | 1105Mak0000043913 | St | Fenstermakro, -SmartPart | 4.9494 | 0 | 70 | 70 | 70 | 70 | 0 | 0.9 | 35 | RC 2 | F_Typ1 | Typ 1 | AllplanAttributes (Fenster) - ash D_Plannummer: D1726; Gewerk: Fensterarbeiten; Positionsnummer_Text: U23; Pset_WindowCommon - Status: NEW; IsExternal: yes
Fenster | H2 Ebene 0 | 2.5 | 2.5 | WINDOW | 0 | E00 | 3.0 | Fenster | MainObject | SmartPartCompressed | 100 | 6.1 | 0 | FA-1FR-D-1S-X-E00-042 | 0,51 | Window | 1116Rau0000066333 | 1105Mak0000043787 | St | Fenstermakro, -SmartPart | 4.9494 | 0 | 70 | 70 | 70 | 70 | 0 | 0.9 | 35 | RC 2 | F_Typ2 | AllplanAttributes (Fenster) - Gewerk: Fensterarbeiten; Positionsnummer_Text: U23; Pset_WindowCommon - Status: NEW; IsExternal: yes
Fenster | H2 Ebene 0 | 2.5 | 2.5 | WINDOW | 0 | E00 | 3.0 | Fenster | MainObject | SmartPartCompressed | 100 | 6.1 | 0 | FA-1FL-D-1S-X-E00-039 | 0,51 | Window | 1116Rau0000065852 | 1105Mak0000046636 | St | Fenstermakro, -SmartPart | 4.9494 | 0 | 70 | 70 | 70 | 70 | 0 | 0.9 | 32 | RC 2 | F_Typ1 | Typ 1 | AllplanAttributes (Fenster) - ash D_Plannummer: D1726; Gewerk: Fensterarbeiten; Positionsnummer_Text: U23; Pset_WindowCommon - Status: NEW; IsExternal: yes
Fenster | H2 Ebene 0 | 2.5 | 2.5 | WINDOW | 0 | E00 | 3.0 | Fenster | MainObject | SmartPartCompressed | 100 | 6.1 | 0 | FA-1FL-D-1S-X-E00-038 | 0,51 | Window | 1116Rau0000065852 | 1105Mak2005793908 | St | Fenstermakro, -SmartPart | 4.9494 | 0 | 70 | 70 | 70 | 70 | 0 | 0.9 | 32 | RC 2 | F_Typ1 | Typ 1 | AllplanAttributes (Fenster) - ash D_Plannummer: D1726; Gewerk: Fensterarbeiten; Positionsnummer_Text: U23; Pset_WindowCommon - Status: NEW; IsExternal: yes
Fenster | H2 Ebene 0 | 2.5 | 2.5 | WINDOW | 0 | E00 | 3.0 | Fenster | MainObject | SmartPartCompressed | 100 | 6.1 | 0 | FA-1FL-D-1S-X-E00-033 | 0,51 | Window | 1116Rau0000066838 | 1105Mak0000046468 | St | Fenstermakro, -SmartPart | 4.9494 | 0 | 70 | 70 | 70 | 70 | 0 | 0.9 | 32 | RC 2 | F_Typ1 | Typ 1 | AllplanAttributes (Fenster) - ash D_Plannummer: D1726; Gewerk: Fensterarbeiten; Positionsnummer_Text: U23; Pset_WindowCommon - Status: NEW; IsExternal: yes
Fenster | H2 Ebene 0 | 2.5 | 1.25 | WINDOW | 0 | E00 | 3.0 | Fenster | MainObject | SmartPartCompressed | 100 | 6.1 | 0 | FA-1FR-D-1S-E00-022 | 0,35 | Window | 1116Rau0000066366 | 1105Mak0811566859 | St | Fenstermakro, -SmartPart | 2.1694 | 0 | 70 | 70 | 70 | 70 | 0 | 0.9 | 32 | RC 2 | F_Typ4 | Typ 4 | AllplanAttributes (Fenster) - ash D_Plannummer: D1727; Gewerk: Fensterarbeiten; Positionsnummer_Text: U23; Pset_WindowCommon - Status: NEW; IsExternal: yes
Fenster | H2 Ebene 0 | 2.5 | 2.5 | WINDOW | 0 |  | 3.0 | Fenster | MainObject | SmartPartCompressed | 100 | 6.1 |  | FA-1FR-D-1S-X-E00-017 | 0,51 |  | 1116Rau0000066574 | 1105Mak0000040141 | St | Fenstermakro, -SmartPart | 4.9494 | 0 | 70 | 70 | 70 | 70 | 0 | 0.9 | 35 | RC 2 | F_Typ2 | AllplanAttributes (Fenster) - Positionsnummer_Text: U23
Fenster | H2 Ebene 0 | 2.12 | 1.35 | WINDOW | 0 | E00 | 3.0 | Fenster | MainObject | SmartPartCompressed | 100 | 6.1 | 0 | FA-1FL-D-1S-E00-L010 | 0,35 | Window | 1116Rau0000066366 | 1105Mak0000050037 | St | Fenstermakro, -SmartPart | 2.0002 | 0 | 70 | 70 | 70 | 70 | 0 | 0.9 | 32 | - | F_Typ3A | Typ 3 | AllplanAttributes (Fenster) - ash D_Plannummer: D1727; Gewerk: Fensterarbeiten; Positionsnummer_Text: U23; Pset_WindowCommon - Status: NEW; IsExternal: yes
Fenster | H2 Ebene 0 | 2.12 | 1.35 | WINDOW | 0 | E00 | 3.0 | Fenster | MainObject | SmartPartCompressed | 100 | 6.1 | 0 | FA-1FL-D-1S-E00-L011 | 0,35 | Window | 1116Rau0000066366 | 1105Mak0000049995 | St | Fenstermakro, -SmartPart | 2.0002 | 0 | 70 | 70 | 70 | 70 | 0 | 0.9 | 32 | - | F_Typ3A | Typ 3 | AllplanAttributes (Fenster) - ash D_Plannummer: D1727; Gewerk: Fensterarbeiten; Positionsnummer_Text: U23; Pset_WindowCommon - Status: NEW; IsExternal: yes
Fenster | H2 Ebene 0 | 2.12 | 1.35 | WINDOW | 0 | E00 | 3.0 | Fenster | MainObject | SmartPartCompressed | 100 | 6.1 | 0 | FA-1FL-D-1S-E00-L016 | 0,35 | Window | 1116Rau0000066366 | 1105Mak2005775928 | St | Fenstermakro, -SmartPart | 2.0002 | 0 | 70 | 70 | 70 | 70 | 0 | 0.9 | 32 | - | F_Typ3A | Typ 3 | AllplanAttributes (Fenster) - ash D_Plannummer: D1727; Gewerk: Fensterarbeiten; Positionsnummer_Text: U23; Pset_WindowCommon - Status: NEW; IsExternal: yes
Fenster | H2 Ebene 0 | 2.12 | 1.35 | WINDOW | 0 | E00 | 3.0 | Fenster | MainObject | SmartPartCompressed | 100 | 6.1 | 0 | FA-1FL-D-1S-E00-L015 | 0,35 | Window | 1116Rau0000066366 | 1105Mak0000049911 | St | Fenstermakro, -SmartPart | 2.0002 | 0 | 70 | 70 | 70 | 70 | 0 | 0.9 | 32 | - | F_Typ3A | Typ 3 | AllplanAttributes (Fenster) - ash D_Plannummer: D1727; Gewerk: Fensterarbeiten; Positionsnummer_Text: U23; Pset_WindowCommon - Status: NEW; IsExternal: yes
Fenster | H2 Ebene 0 | 2.12 | 1.35 | WINDOW | 0 | E00 | 3.0 | Fenster | MainObject | SmartPartCompressed | 100 | 6.1 | 0 | FA-1FL-D-1S-E00-L012 | 0,35 | Window | 1116Rau0000066366 | 1105Mak0000049953 | St | Fenstermakro, -SmartPart | 2.0002 | 0 | 70 | 70 | 70 | 70 | 0 | 0.9 | 32 | - | F_Typ3A | Typ 3 | AllplanAttributes (Fenster) - ash D_Plannummer: D1727; Gewerk: Fensterarbeiten; Positionsnummer_Text: U23; Pset_WindowCommon - Status: NEW; IsExternal: yes
Fenster | H2 Ebene 0 | 2.5 | 1.25 | WINDOW | 0 | E00 | 3.0 | Fenster | MainObject | SmartPartCompressed | 100 | 6.1 | 0 | FA-1FL-D-1S-E00-028 | 0,35 | Window | 1116Rau0000066366 | 1105Mak0000047431 | St | Fenstermakro, -SmartPart | 2.1694 | 0 | 70 | 70 | 70 | 70 | 0 | 0.9 | 32 | RC 2 | F_Typ3 | Typ 3 | AllplanAttributes (Fenster) - ash D_Plannummer: D1727; Gewerk: Fensterarbeiten; Positionsnummer_Text: U23; Pset_WindowCommon - Status: NEW; IsExternal: yes
Fenster | H2 Ebene 0 | 2.79 | 2.3945 | WINDOW | 0 |  | 2.2 | Fenster | MainObject | SmartPartCompressed | 100 | 4.1 |  |  |  |  |  | 1105Mak2005671340 | St | Fenstermakro, -SmartPart | 5.4078 | 0 | 140 | 0 | 0 | 0 |  | 0 |  |  | Codetext | AllplanAttributes (Fenster) - Codetext: Codetext; Gewerk: Metallbau-, Schlosserarbeiten; Funktion: Funktion; Glasart: Glasart; Typ: Typ; Fluchtweg: no; Pset_DoorWindowGlazingType - Shading Coefficient: 0; Pset_WindowCommon - Status: NEW; IsExternal: yes; SmokeStop: no
Fenster | H2 Ebene 0 | 2.79 | 2.418 | WINDOW | 0 |  | 2.2 | Fenster | MainObject | SmartPartCompressed | 100 | 4.1 |  |  |  |  |  | 1105Mak2005674044 | St | Fenstermakro, -SmartPart | 5.46678 | 0 | 140 | 0 | 0 | 0 |  | 0 |  |  | Codetext | AllplanAttributes (Fenster) - Codetext: Codetext; Gewerk: Metallbau-, Schlosserarbeiten; Funktion: Funktion; Glasart: Glasart; Typ: Typ; Fluchtweg: no; Pset_DoorWindowGlazingType - Shading Coefficient: 0; Pset_WindowCommon - Status: NEW; IsExternal: yes; SmokeStop: no
Fenster | H2 Ebene 0 | 2.26 | 1.848 | WINDOW | 0 | E00 | 3.0 | Fenster | MainObject | SmartPartCompressed | 100 | 6.1 | 0 | FA-1FL-D-1S-X-E00-053 | 0,35 | Window | 1115Rau0000005181 | 1105Mak2005677936 | St | Fenstermakro, -SmartPart | 3.15177 | 0 | 70 | 70 | 70 | 70 | 0 | 0.9 | - | RC 2 | F_Typ9 | AllplanAttributes (Fenster) - Gewerk: Fensterarbeiten; Positionsnummer_Text: U23; Pset_WindowCommon - Status: NEW; IsExternal: yes
Fenster | H2 Ebene 0 | 2.12 | 1.35 | WINDOW | 0 | E00 | 3.0 | Fenster | MainObject | SmartPartCompressed | 100 | 6.1 | 0 | FA-1FR-D-1S-E00-L031 | 0,35 | Window | 1116Rau0000066366 | 1105Mak2005780622 | St | Fenstermakro, -SmartPart | 2.0002 | 0 | 70 | 70 | 70 | 70 | 0 | 0.9 | 32 | - | F_Typ4A | AllplanAttributes (Fenster) - Gewerk: Fensterarbeiten; Positionsnummer_Text: U23; Pset_WindowCommon - Status: NEW; IsExternal: yes
Fenster | H2 Ebene 0 | 2.5 | 2.5 | WINDOW | 0 | E00 | 3.0 | Fenster | MainObject | SmartPartCompressed | 100 | 6.1 | 0 | FA-1FR-D-1S-X-E00-055 | 0,51 | Window | 1116Rau0000066294 | 1105Mak0000041082 | St | Fenstermakro, -SmartPart | 4.9494 | 0 | 70 | 70 | 70 | 70 | 0 | 0.9 | 39 | RC 2 | F_Typ2 | AllplanAttributes (Fenster) - Gewerk: Fensterarbeiten; Positionsnummer_Text: U23; Pset_WindowCommon - Status: NEW; IsExternal: yes
Fenster | H2 Ebene 0 | 2.5 | 2.5 | WINDOW | 0 | E00 | 3.0 | Fenster | MainObject | SmartPartCompressed | 100 | 6.1 | 0 | FA-1FL-D-1S-X-E00-056 | 0,51 | Window | 1116Rau0000066297 | 1105Mak0000041166 | St | Fenstermakro, -SmartPart | 4.9494 | 0 | 70 | 70 | 70 | 70 | 0 | 0.9 | 39 | RC 2 | F_Typ1 | Typ 1 | AllplanAttributes (Fenster) - ash D_Plannummer: D1726; Gewerk: Fensterarbeiten; Positionsnummer_Text: U23; Pset_WindowCommon - Status: NEW; IsExternal: yes
Fenster | H2 Ebene 0 | 2.17 | 2.28 | WINDOW | 0 | E00 | 3.0 | Fenster | MainObject | SmartPartCompressed | 100 | 7.2 | 0 | FA-F-E00-061 | 0,49 | Window | 1105Mak0811560435 | 1105Mak0811560435 | St | Fenstermakro, -SmartPart | 4.2021 | 0 | 70 | 70 | 70 | 70 | EI 60 | 2 | - | RC 2 | F_Typ8 | AllplanAttributes (Fenster) - Gewerk: Zimmer- und Holzbauarbeiten; Selbstschließend: no; ash T_Zulage Schachttür: no; ash T_Dichtschließend: no; ash T_Feststellanlage (FSA): -; ash T_nicht abschließbar: no; Positionsnummer_Text: U23; Pset_WindowCommon - SmokeStop: yes
Fenster | H2 Ebene 0 | 2.26 | 1.848 | WINDOW | 0 | E00 | 3.0 | Fenster | MainObject | SmartPartCompressed | 100 | 6.1 | 0 | FA-1FR-D-1S-X-E00-049 | 0,35 | Window | 1115Rau0000005181 | 1105Mak2005765896 | St | Fenstermakro, -SmartPart | 3.15177 | 0 | 70 | 70 | 70 | 70 | 0 | 0.9 | - | RC 2 | F_Typ10 | AllplanAttributes (Fenster) - Gewerk: Fensterarbeiten; Positionsnummer_Text: U23; Pset_WindowCommon - Status: NEW; IsExternal: yes
Fenster | H2 Ebene 0 | 2.52 | 0.675 | WINDOW | 0 | E00 | 3.0 | Fenster | MainObject | SmartPartCompressed | 100 | 6.1 | 0 | FA-F-E00-L003 | 0,35 | Window | 1116Rau0000065738 | 1105Mak2005785719 | St | Fenstermakro, -SmartPart | 1.2733 | 0 | 70 | 70 | 70 | 70 | 0 | 0.9 | 32 | - | F_Typ6 | AllplanAttributes (Fenster) - Gewerk: Fensterarbeiten; Positionsnummer_Text: U23; Pset_WindowCommon - Status: NEW; IsExternal: yes
Fenster | H2 Ebene 0 | 2.12 | 1.35 | WINDOW | 0 | E00 | 3.0 | Fenster | MainObject | SmartPartCompressed | 100 | 6.1 | 0 | FA-1FR-D-1S-E00-L021 | 0,35 | Window | 1116Rau0000066366 | 1105Mak2005785497 | St | Fenstermakro, -SmartPart | 2.0002 | 0 | 70 | 70 | 70 | 70 | 0 | 0.9 | 32 | - | F_Typ4A | AllplanAttributes (Fenster) - Gewerk: Fensterarbeiten; Positionsnummer_Text: U23; Pset_WindowCommon - Status: NEW; IsExternal: yes
Fenster | H2 Ebene 0 | 2.12 | 1.35 | WINDOW | 0 | E00 | 3.0 | Fenster | MainObject | SmartPartCompressed | 100 | 6.1 | 0 | FA-1FR-D-1S-E00-L020 | 0,35 | Window | 1116Rau0000066366 | 1105Mak2005785415 | St | Fenstermakro, -SmartPart | 2.0002 | 0 | 70 | 70 | 70 | 70 | 0 | 0.9 | 32 | - | F_Typ4A | AllplanAttributes (Fenster) - Gewerk: Fensterarbeiten; Positionsnummer_Text: U23; Pset_WindowCommon - Status: NEW; IsExternal: yes
Fenster | H2 Ebene 0 | 2.12 | 1.35 | WINDOW | 0 | E00 | 3.0 | Fenster | MainObject | SmartPartCompressed | 100 | 6.1 | 0 | FA-1FR-D-1S-E00-L019 | 0,35 | Window | 1116Rau0000066366 | 1105Mak2005785253 | St | Fenstermakro, -SmartPart | 2.0002 | 0 | 70 | 70 | 70 | 70 | 0 | 0.9 | 32 | - | F_Typ4A | AllplanAttributes (Fenster) - Gewerk: Fensterarbeiten; Positionsnummer_Text: U23; Pset_WindowCommon - Status: NEW; IsExternal: yes
Fenster | H2 Ebene 0 | 2.12 | 1.35 | WINDOW | 0 | E00 | 3.0 | Fenster | MainObject | SmartPartCompressed | 100 | 6.1 | 0 | FA-1FR-D-1S-E00-L018 | 0,35 | Window | 1116Rau0000066366 | 1105Mak0000180440 | St | Fenstermakro, -SmartPart | 2.0002 | 0 | 70 | 70 | 70 | 70 | 0 | 0.9 | 32 | - | F_Typ4A | AllplanAttributes (Fenster) - Gewerk: Fensterarbeiten; Positionsnummer_Text: U23; Pset_WindowCommon - Status: NEW; IsExternal: yes
Fenster | H2 Ebene 0 | 2.52 | 0.675 | WINDOW | 0 | E00 | 3.0 | Fenster | MainObject | SmartPartCompressed | 100 | 6.1 | 0 | FA-F-E00-L003 | 0,35 | Window | 1116Rau0000065738 | 1105Mak2005785579 | St | Fenstermakro, -SmartPart | 1.2733 | 0 | 70 | 70 | 70 | 70 | 0 | 0.9 | 32 | - | F_Typ6 | AllplanAttributes (Fenster) - Gewerk: Fensterarbeiten; Positionsnummer_Text: U23; Pset_WindowCommon - Status: NEW; IsExternal: yes
Fenster | H2 Ebene 0 | 2.12 | 1.35 | WINDOW | 0 | E00 | 3.0 | Fenster | MainObject | SmartPartCompressed | 100 | 6.1 | 0 | FA-1FL-D-1S-E00-L017a | 0,35 | Window | 1116Rau0000066366 | 1105Mak2005776752 | St | Fenstermakro, -SmartPart | 2.0002 | 0 | 70 | 70 | 70 | 70 | 0 | 0.9 | 32 | - | F_Typ3A | Typ 3 | AllplanAttributes (Fenster) - ash D_Plannummer: D1727; Gewerk: Fensterarbeiten; Positionsnummer_Text: U23; Pset_WindowCommon - Status: NEW; IsExternal: yes
Fenster | H2 Ebene 0 | 2.12 | 1.35 | WINDOW | 0 | E00 | 3.0 | Fenster | MainObject | SmartPartCompressed | 100 | 6.1 | 0 | FA-1FL-D-1S-E00-L017b | 0,35 | Window | 1116Rau0000066366 | 1105Mak2005776914 | St | Fenstermakro, -SmartPart | 2.0002 | 0 | 70 | 70 | 70 | 70 | 0 | 0.9 | 32 | - | F_Typ3A | Typ 3 | AllplanAttributes (Fenster) - ash D_Plannummer: D1727; Gewerk: Fensterarbeiten; Positionsnummer_Text: U23; Pset_WindowCommon - Status: NEW; IsExternal: yes
Fenster | H2 Ebene 0 | 2.12 | 1.35 | WINDOW | 0 | E00 | 3.0 | Fenster | MainObject | SmartPartCompressed | 100 | 6.1 | 0 | FA-1FL-D-1S-E00-L017c | 0,35 | Window | 1116Rau0000066366 | 1105Mak2005777031 | St | Fenstermakro, -SmartPart | 2.0002 | 0 | 70 | 70 | 70 | 70 | 0 | 0.9 | 32 | - | F_Typ3A | Typ 3 | AllplanAttributes (Fenster) - ash D_Plannummer: D1727; Gewerk: Fensterarbeiten; Positionsnummer_Text: U23; Pset_WindowCommon - Status: NEW; IsExternal: yes
Fenster | H2 Ebene 0 | 2.5 | 2.5 | WINDOW | 0 | E00 | 3.0 | Fenster | MainObject | SmartPartCompressed | 100 | 6.1 | 0 | FA-1FL-D-1S-X-E00-054 | 0,51 | Window | 1116Rau0000066560 | 1105Mak0000041124 | St | Fenstermakro, -SmartPart | 4.9494 | 0 | 70 | 70 | 70 | 70 | 0 | 0.9 | 39 | RC 2 | F_Typ1 | Typ 1 | AllplanAttributes (Fenster) - ash D_Plannummer: D1726; Gewerk: Fensterarbeiten; Positionsnummer_Text: U23; Pset_WindowCommon - Status: NEW; IsExternal: yes
Fenster | H2 Ebene 0 | 2.5 | 2.5 | WINDOW | 0 | E00 | 3.0 | Fenster | MainObject | SmartPartCompressed | 100 | 6.1 | 0 | FA-1FL-D-1S-X-E00-060 | 0,51 | Window | 1116Rau0000066303 | 1105Mak0811559594 | St | Fenstermakro, -SmartPart | 4.9494 | 0 | 70 | 70 | 70 | 70 | 0 | 0.9 | 42 | RC 2 | F_Typ1 | Typ 1 | AllplanAttributes (Fenster) - ash D_Plannummer: D1726; Gewerk: Fensterarbeiten; Positionsnummer_Text: U23; Pset_WindowCommon - Status: NEW; IsExternal: yes
Fenster | H2 Ebene 0 | 2.5 | 2.5 | WINDOW | 0 | E00 | 3.0 | Fenster | MainObject | SmartPartCompressed | 100 | 6.1 | 0 | FA-1FR-D-1S-X-E00-059 | 0,51 | Window | 1116Rau0000066300 | 1105Mak0811559638 | St | Fenstermakro, -SmartPart | 4.9494 | 0 | 70 | 70 | 70 | 70 | 0 | 0.9 | 42 | RC 2 | F_Typ2 | AllplanAttributes (Fenster) - Gewerk: Fensterarbeiten; Positionsnummer_Text: U23; Pset_WindowCommon - Status: NEW; IsExternal: yes
Fenster | H2 Ebene 0 | 2.1 | 1.25 | WINDOW | 0 | E00 | 3.0 | Fenster | MainObject | SmartPartCompressed | 100 | 6.1 | 0 | FA-1FL-D-1S-E00-052 | 0,35 | Window | 1116Rau0000066366 | 1105Mak0000538349 | St | Fenstermakro, -SmartPart | 1.7934 | 0 | 70 | 70 | 70 | 70 | 0 | 0.9 | 32 | RC 2 | F_Typ3 | Typ 3 | AllplanAttributes (Fenster) - ash D_Plannummer: D1727; Gewerk: Fensterarbeiten; Positionsnummer_Text: U23; Pset_WindowCommon - Status: NEW; IsExternal: yes
Fenster | H2 Ebene 0 | 1.88 | 0.64994 | WINDOW | 0 | E00 | 3.0 | Fenster | MainObject | SmartPartCompressed | 100 | 7.2 | 0 | FI-E00-012-001-002 |  | Window | 1116Rau0000066462 | 1113Mak0813442862 | St | Fenstermakro, -SmartPart | 1.22189 | 0 | 0 | 0 | 0 | 0 | EI 30 | AllplanAttributes (Fenster) - Gewerk: Zimmer- und Holzbauarbeiten; Selbstschließend: no; ash T_Zulage Schachttür: no; ash T_Dichtschließend: no; ash T_Feststellanlage (FSA): -; ash T_nicht abschließbar: yes; ash T_Schallschutz: 24 dB; Positionsnummer_Text: S68; Pset_WindowCommon - SmokeStop: yes
Fenster | H2 Ebene 0 | 1.88 | 0.64994 | WINDOW | 0 | E00 | 3.0 | Fenster | MainObject | SmartPartCompressed | 100 | 7.2 | 0 | FI-E00-012-001-002 |  | Window | 1116Rau0000066462 | 1113Mak0813443012 | St | Fenstermakro, -SmartPart | 1.22189 | 0 | 0 | 0 | 0 | 0 | EI 30 | AllplanAttributes (Fenster) - Gewerk: Zimmer- und Holzbauarbeiten; Selbstschließend: no; ash T_Zulage Schachttür: no; ash T_Dichtschließend: no; ash T_Feststellanlage (FSA): -; ash T_nicht abschließbar: yes; ash T_Schallschutz: 24 dB; Positionsnummer_Text: S68; Pset_WindowCommon - SmokeStop: yes
wi_1c_white | H2 Ebene 0 | 1.18 | 1.91263 | WINDOW |  |  |  |  |  |  |  |  |  |  |  |  |  |  |  |  | 1.84354 | 0 | 70 | 70 | 70 | 70 | AllplanAttributes (wi_1c_white) - Leibungstiefe: 0.1 m; V6: 0 m; V7: 0 m; V8: 0 m; V9: 0; Bitfolge_Flügel DINlinks / DINrechts: 0; Bezeichnung: wi_1c_white; Plugin_Bezeichnung: OpeningParts_Object; Plugin_Objektname: OpeningParts_Object; Glasanteil_berücksichtigen: 100; Version: 1.0; P_ID: 1113Mak0814185315; Allright_Bauteil_ID: 1113Mak0814280894; Abrechnungsart: St; Objektname: Fenstermakro, -SmartPart
wi_1c_white | H2 Ebene 0 | 1.51 | 2.18475 | WINDOW |  |  |  |  |  |  |  |  |  |  |  |  |  |  |  |  | 1.95764 | 0 | 50 | 50 | 50 | 50 | AllplanAttributes (wi_1c_white) - Leibungstiefe: 0.08 m; V6: 0 m; V7: 0 m; V8: 0 m; V9: 0; Bitfolge_Flügel DINlinks / DINrechts: 0; Bezeichnung: wi_1c_white; Plugin_Bezeichnung: OpeningParts_Object; Plugin_Objektname: OpeningParts_Object; Glasanteil_berücksichtigen: 100; Version: 1.0; P_ID: 1113Mak0814021229; Allright_Bauteil_ID: 1113Mak0814021229; Abrechnungsart: St; Objektname: Fenstermakro, -SmartPart; ash D_Detailverweis: D6; ash D_Plannummer: 1684
Fenster | H2 Ebene 0 | 1.31 | 1.6 | WINDOW | 0 | E00 | 3.0 | Fenster | MainObject | SmartPartCompressed | 100 | 7.2 | 0 | FI-E00-012-001-002 |  | Window | 1116Rau0000066462 | 1113Mak0813940829 | St | Fenstermakro, -SmartPart | 1.7082 | 0 | 70 | 70 | 70 | 70 | EI 30 | AllplanAttributes (Fenster) - Gewerk: Zimmer- und Holzbauarbeiten; Selbstschließend: no; ash T_Zulage Schachttür: no; ash T_Dichtschließend: no; ash T_Feststellanlage (FSA): -; ash T_nicht abschließbar: yes; ash T_Schallschutz: 24 dB; Positionsnummer_Text: S68; Pset_WindowCommon - SmokeStop: yes; AllplanAttributes (TGR 1.5) - Codetext: Typ; V6: 0 m; V7: 0 m; V8: 0 m; V9: 0; Programmversion: 3.1; Objektname: TGR-Makro; Text1: PlanNo.; Bezeichnung: TGR 1.5; Plugin_Bezeichnung: MainObject; Plugin_Objektname: SmartPartCompressed; Gesamtlänge: 8.855; Version: 1.5; OKFF: 0; ash T_Türprofilnummer: 7; Positionsnummer_Text: S68; P_ID: 1115Rau0000005189; Allright_Bauteil_ID: 1113Mak0813941129; Abrechnungsart: St
Fenster | H2 Ebene 0 | 2.75 | 2.569 | WINDOW | 0 | E00 | 3.0 | Fenster | MainObject | SmartPartCompressed | 100 | 7.2 | 0 |  |  | Window | 1115Rau0000005189 | 1113Mak0812934787 | St | Fenstermakro, -SmartPart | 5.95023 | 0 | 200 | 80 | 80 | 80 | EI2 60 | AllplanAttributes (Fenster) - Gewerk: Zimmer- und Holzbauarbeiten; Selbstschließend: no; ash T_Zulage Schachttür: no; ash T_Dichtschließend: no; ash T_Feststellanlage (FSA): -; ash T_nicht abschließbar: yes; ash T_Schallschutz: -; Positionsnummer_Text: S68; Pset_WindowCommon - SmokeStop: no
Fenster | H2 Ebene 0 | 2.75 | 2.569 | WINDOW | 0 | E00 | 3.0 | Fenster | MainObject | SmartPartCompressed | 100 | 7.2 | 0 |  |  | Window | 1115Rau0000005189 | 1113Mak0812935050 | St | Fenstermakro, -SmartPart | 5.95023 | 0 | 200 | 80 | 80 | 80 | EI2 60 | AllplanAttributes (Fenster) - Gewerk: Zimmer- und Holzbauarbeiten; Selbstschließend: no; ash T_Zulage Schachttür: no; ash T_Dichtschließend: no; ash T_Feststellanlage (FSA): -; ash T_nicht abschließbar: yes; ash T_Schallschutz: -; Positionsnummer_Text: S68; Pset_WindowCommon - SmokeStop: no
Fenster | H2 Ebene 0 | 1.31 | 1.6 | WINDOW | 0 | E00 | 3.0 | Fenster | MainObject | SmartPartCompressed | 100 | 7.2 | 0 | FI-E00-012-001-002 |  | Window | 1116Rau0000066462 | 1113Mak0813939392 | St | Fenstermakro, -SmartPart | 1.7082 | 0 | 70 | 70 | 70 | 70 | EI 30 | AllplanAttributes (Fenster) - Gewerk: Zimmer- und Holzbauarbeiten; Selbstschließend: no; ash T_Zulage Schachttür: no; ash T_Dichtschließend: no; ash T_Feststellanlage (FSA): -; ash T_nicht abschließbar: yes; ash T_Schallschutz: 24 dB; Positionsnummer_Text: S68; Pset_WindowCommon - SmokeStop: yes
Fenster | H2 Ebene 0 | 1.79 | 4.5972 | WINDOW | 0 | E00 | 3.0 | Fenster | MainObject | SmartPartCompressed | 100 | 7.2 | 0 |  |  | Window | 1113Mak0814189306 | 1113Mak0814189306 | St | Fenstermakro, -SmartPart | 7.76928 | 0 | 50 | 0 | 0 | 50 | EI 30 |  |  |  |  | D5 | AllplanAttributes (Fenster) - ash D_Plannummer: 1684; Gewerk: Zimmer- und Holzbauarbeiten; Selbstschließend: no; ash T_Zulage Schachttür: no; ash T_Dichtschließend: no; ash T_Feststellanlage (FSA): -; ash T_nicht abschließbar: yes; ash T_Schallschutz: 24 dB; Positionsnummer_Text: S68; Pset_WindowCommon - SmokeStop: yes
Fenster | H2 Ebene 0 | 1.54 | 1.46452 | WINDOW | 0 | E00 | 3.0 | Fenster | MainObject | SmartPartCompressed | 100 | 7.2 | 0 |  |  | Window | 1113Mak0814189208 | 1113Mak0814233629 | St | Fenstermakro, -SmartPart | 2.03691 | 0 | 50 | 0 | 50 | 50 | EI 30 | AllplanAttributes (Fenster) - Gewerk: Zimmer- und Holzbauarbeiten; Selbstschließend: no; ash T_Zulage Schachttür: no; ash T_Dichtschließend: no; ash T_Feststellanlage (FSA): -; ash T_nicht abschließbar: yes; ash T_Schallschutz: 24 dB; Positionsnummer_Text: S68; Pset_WindowCommon - SmokeStop: yes
Fenster | H2 Ebene 0 | 1.54 | 1.46471 | WINDOW | 0 | E00 | 3.0 | Fenster | MainObject | SmartPartCompressed | 100 | 7.2 | 0 |  |  | Window | 1113Mak0814215023 | 1113Mak0814215023 | St | Fenstermakro, -SmartPart | 2.03718 | 0 | 50 | 50 | 0 | 50 | EI 30 | AllplanAttributes (Fenster) - Gewerk: Zimmer- und Holzbauarbeiten; Selbstschließend: no; ash T_Zulage Schachttür: no; ash T_Dichtschließend: no; ash T_Feststellanlage (FSA): -; ash T_nicht abschließbar: yes; ash T_Schallschutz: 24 dB; Positionsnummer_Text: S68; Pset_WindowCommon - SmokeStop: yes
wi_1c_white | H2 Ebene 0 | 1.18 | 1.0425 | WINDOW |  |  |  |  |  |  |  |  |  |  |  |  |  |  |  |  | 0.938596 | 0 | 70 | 70 | 70 | 70 | AllplanAttributes (wi_1c_white) - Leibungstiefe: 0.1 m; V6: 0 m; V7: 0 m; V8: 0 m; V9: 0; Bitfolge_Flügel DINlinks / DINrechts: 0; Bezeichnung: wi_1c_white; Plugin_Bezeichnung: OpeningParts_Object; Plugin_Objektname: OpeningParts_Object; Glasanteil_berücksichtigen: 100; Version: 1.0; Allright_Bauteil_ID: 1113Mak0814280891; Abrechnungsart: St; Objektname: Fenstermakro, -SmartPart
wi_1c_white | H2 Ebene 0 | 1.51 | 2.22 | WINDOW |  |  |  |  |  |  |  |  |  |  |  |  |  |  |  |  | 1.95764 | 0 | 50 | 50 | 50 | 50 | AllplanAttributes (wi_1c_white) - Leibungstiefe: 0.08 m; V6: 0 m; V7: 0 m; V8: 0 m; V9: 0; Bitfolge_Flügel DINlinks / DINrechts: 0; Bezeichnung: wi_1c_white; Plugin_Bezeichnung: OpeningParts_Object; Plugin_Objektname: OpeningParts_Object; Glasanteil_berücksichtigen: 100; Version: 1.0; Allright_Bauteil_ID: 1113Mak0814190712; Abrechnungsart: St; Objektname: Fenstermakro, -SmartPart
wi_1c_white | H2 Ebene 0 | 1.18 | 3.0949 | WINDOW |  |  |  |  |  |  |  |  |  |  |  |  |  |  |  |  | 1.95764 | 0 | 50 | 50 | 50 | 50 | AllplanAttributes (wi_1c_white) - Leibungstiefe: 0.08 m; V6: 0 m; V7: 0 m; V8: 0 m; V9: 0; Bitfolge_Flügel DINlinks / DINrechts: 0; Bezeichnung: wi_1c_white; Plugin_Bezeichnung: OpeningParts_Object; Plugin_Objektname: OpeningParts_Object; Glasanteil_berücksichtigen: 100; Version: 1.0; Allright_Bauteil_ID: 1113Mak0814266510; Abrechnungsart: St; Objektname: Fenstermakro, -SmartPart; ash D_Detailverweis: D6; ash D_Plannummer: 1684
wi_1c_white | H2 Ebene 0 | 1.18 | 1.05 | WINDOW |  |  |  |  |  |  |  |  |  |  |  |  |  |  |  |  | 1.57227 | 0 | 120 | 120 | 120 | 120 | AllplanAttributes (wi_1c_white) - Leibungstiefe: 0.08 m; V6: 0 m; V7: 0 m; V8: 0 m; V9: 0; Bitfolge_Flügel DINlinks / DINrechts: 0; Bezeichnung: wi_1c_white; Plugin_Bezeichnung: OpeningParts_Object; Plugin_Objektname: OpeningParts_Object; Glasanteil_berücksichtigen: 100; Version: 1.0; Allright_Bauteil_ID: 1113Mak0814281159; Abrechnungsart: St; Objektname: Fenstermakro, -SmartPart; ash D_Detailverweis: D6; ash D_Plannummer: 1684
Symbol BD | H2 Ebene 0 | 1.5 | 0.681 | SKYLIGHT | AllplanAttributes (Symbol BD) - V6: 0 m; V7: 0 m; V8: 0 m; V9: 0; Programmversion: 3.0; Objektname: Bodendurchbruchsmakro; Bezeichnung: Symbol BD; Plugin_Bezeichnung: MainObject; Plugin_Objektname: SmartPartCompressed; Version: 1.0; Attributset-Objekt: Opening; Allright_Bauteil_ID: 1114Mak0000015284; Abrechnungsart: St
Symbol BD | H2 Ebene 0 | 0.611 | 3.8 | SKYLIGHT | AllplanAttributes (Symbol BD) - V6: 0 m; V7: 0 m; V8: 0 m; V9: 0; Programmversion: 3.0; Objektname: Bodendurchbruchsmakro; Bezeichnung: Symbol BD; Plugin_Bezeichnung: MainObject; Plugin_Objektname: SmartPartCompressed; Version: 1.0; Attributset-Objekt: Opening; Allright_Bauteil_ID: 1114Mak0000003988; Abrechnungsart: St
Symbol BD | H2 Ebene 0 | 1.1275 | 3 | SKYLIGHT | AllplanAttributes (Symbol BD) - V6: 0 m; V7: 0 m; V8: 0 m; V9: 0; Programmversion: 3.0; Objektname: Bodendurchbruchsmakro; Bezeichnung: Symbol BD; Plugin_Bezeichnung: MainObject; Plugin_Objektname: SmartPartCompressed; Version: 1.0; Attributset-Objekt: Opening; Allright_Bauteil_ID: 1114Mak0000003989; Abrechnungsart: St
Symbol BD | H2 Ebene 0 | 0.681 | 1.5 | SKYLIGHT | AllplanAttributes (Symbol BD) - V6: 0 m; V7: 0 m; V8: 0 m; V9: 0; Programmversion: 3.0; Objektname: Bodendurchbruchsmakro; Bezeichnung: Symbol BD; Plugin_Bezeichnung: MainObject; Plugin_Objektname: SmartPartCompressed; Version: 1.0; Attributset-Objekt: Opening; Allright_Bauteil_ID: 1114Mak0000003984; Abrechnungsart: St
Symbol BD | H2 Ebene 0 | 0.511 | 1.65 | SKYLIGHT | AllplanAttributes (Symbol BD) - V6: 0 m; V7: 0 m; V8: 0 m; V9: 0; Programmversion: 3.0; Objektname: Bodendurchbruchsmakro; Bezeichnung: Symbol BD; Plugin_Bezeichnung: MainObject; Plugin_Objektname: SmartPartCompressed; Version: 1.0; Attributset-Objekt: Opening; Allright_Bauteil_ID: 1114Mak0000003991; Abrechnungsart: St
Symbol BD | H2 Ebene 0 | 0.683 | 1.5 | SKYLIGHT | AllplanAttributes (Symbol BD) - V6: 0 m; V7: 0 m; V8: 0 m; V9: 0; Programmversion: 3.0; Objektname: Bodendurchbruchsmakro; Bezeichnung: Symbol BD; Plugin_Bezeichnung: MainObject; Plugin_Objektname: SmartPartCompressed; Version: 1.0; Attributset-Objekt: Opening; Allright_Bauteil_ID: 1114Mak0000003993; Abrechnungsart: St
Symbol BD | H2 Ebene 0 | 1.1275 | 3 | SKYLIGHT | AllplanAttributes (Symbol BD) - V6: 0 m; V7: 0 m; V8: 0 m; V9: 0; Programmversion: 3.0; Objektname: Bodendurchbruchsmakro; Bezeichnung: Symbol BD; Plugin_Bezeichnung: MainObject; Plugin_Objektname: SmartPartCompressed; Version: 1.0; Attributset-Objekt: Opening; Allright_Bauteil_ID: 1114Mak0000003968; Abrechnungsart: St
Symbol BD | H2 Ebene 0 | 0.68749 | 1.5 | SKYLIGHT | AllplanAttributes (Symbol BD) - V6: 0 m; V7: 0 m; V8: 0 m; V9: 0; Programmversion: 3.0; Objektname: Bodendurchbruchsmakro; Bezeichnung: Symbol BD; Plugin_Bezeichnung: MainObject; Plugin_Objektname: SmartPartCompressed; Version: 1.0; Attributset-Objekt: Opening; Allright_Bauteil_ID: 1114Mak0000003986; Abrechnungsart: St
Symbol BD | H2 Ebene 0 | 3.03 | 2.45001 | SKYLIGHT | AllplanAttributes (Symbol BD) - V6: 0 m; V7: 0 m; V8: 0 m; V9: 0; Programmversion: 3.0; Objektname: Bodendurchbruchsmakro; Bezeichnung: Symbol BD; Plugin_Bezeichnung: MainObject; Plugin_Objektname: SmartPartCompressed; Version: 1.0; Attributset-Objekt: Opening; Allright_Bauteil_ID: 1114Mak0000012498; Abrechnungsart: St
Symbol BD | H2 Ebene 0 | 3.03 | 2.45 | SKYLIGHT | AllplanAttributes (Symbol BD) - V6: 0 m; V7: 0 m; V8: 0 m; V9: 0; Programmversion: 3.0; Objektname: Bodendurchbruchsmakro; Bezeichnung: Symbol BD; Plugin_Bezeichnung: MainObject; Plugin_Objektname: SmartPartCompressed; Version: 1.0; Attributset-Objekt: Opening; Allright_Bauteil_ID: 1114Mak0000012507; Abrechnungsart: St
Symbol BD | H2 Gründung | 3.03 | 2.45 | SKYLIGHT | AllplanAttributes (Symbol BD) - V6: 0 m; V7: 0 m; V8: 0 m; V9: 0; Programmversion: 3.0; Objektname: Bodendurchbruchsmakro; Bezeichnung: Symbol BD; Plugin_Bezeichnung: MainObject; Plugin_Objektname: SmartPartCompressed; Version: 1.0; Attributset-Objekt: Opening; Allright_Bauteil_ID: 1012Mak0811372743; Abrechnungsart: St
Symbol BD | H2 Gründung | 3.03 | 2.44999 | SKYLIGHT | AllplanAttributes (Symbol BD) - V6: 0 m; V7: 0 m; V8: 0 m; V9: 0; Programmversion: 3.0; Objektname: Bodendurchbruchsmakro; Bezeichnung: Symbol BD; Plugin_Bezeichnung: MainObject; Plugin_Objektname: SmartPartCompressed; Version: 1.0; Attributset-Objekt: Opening; Allright_Bauteil_ID: 1012Mak0811372740; Abrechnungsart: St

# IfcWindow: Fenster (21)
Type - PredefinedType: WINDOW; PartitioningType: DOUBLE_PANEL_HORIZONTAL; ParameterTakesPrecedence: no
Type - IfcWindowLiningProperties - LiningDepth: 0.07 m; LiningThickness: 0.07 m
AllplanAttributes (Fenster) - V6: 0 m; V7: 0 m; V8: 0 m; V9: 0; Programmversion: 3.0; Bezeichnung: Fenster; Plugin_Bezeichnung: MainObject; Plugin_Objektname: SmartPartCompressed; Glasanteil_berücksichtigen: 100; Version: 6.1; Abrechnungsart: St; Objektname: Fenstermakro, -SmartPart
AllplanQuantities - HeightWindowSillOutside: 0; HeightWindowSillInside: 0; OffsetOpeningBottom: 0; OffsetOpeningTop: 0; OffsetOpeningLeft: 0; OffsetOpeningRight: 0; DeductionOpeningBottom: 70; DeductionOpeningLeft: 70; DeductionOpeningRight: 70; DeductionOpeningTop: 70
Pset_WindowCommon - FireRating: 0; ThermalTransmittance: 0.9 W/K/m2
Name | In | OverallHeight (m) | OverallWidth (m) | Ortscode_Geschoßbezeichnung | OKFF | ash T_Tür-Nr. | g-Wert | Attributset-Objekt | P_ID | Allright_Bauteil_ID | GlassSurface | AcousticRating | SecurityRating | Reference | Sonnenschutztyp
Fenster | H2 Ebene +3 | 2.5 | 1.25 | E03 | 11.25 | FA_1F-K-E03-200a | 0,35 | Window | 1265Rau0000000005 | 1255Mak0811531376 | 2.2316 | - | - | F_Typ5
Fenster | H2 Ebene +3 | 2.5 | 1.25 | E03 | 11.25 | FA_1F-K-E03-199 | 0,35 | Window | 1265Rau0000000005 | 1255Mak0000013064 | 2.2316 | - | - | F_Typ5
Fenster | H2 Ebene +3 | 2.5 | 1.25 | E03 | 11.25 | FA_1F-K-E03-202 | 0,35 | Window | 1265Rau0000000005 | 1255Mak0000000620 | 2.2316 | - | - | F_Typ5
Fenster | H2 Ebene +3 | 2.5 | 1.25 | E03 | 11.25 | FA_1F-K-E03-201c | 0,35 | Window | 1265Rau0000000005 | 1255Mak0811531502 | 2.2316 | - | - | F_Typ5
Fenster | H2 Ebene +3 | 2.12 | 0.725 | E03 | 11.25 | FA-1FR-D-E03-L149 | 0,51 | Window | 1266Rau0000015290 | 1255Mak0811536846 | 0.9133 | - | - | F_Typ36 | AllplanAttributes (Fenster) - ash D_Detailverweis: Typ36
Fenster | H2 Ebene +2 | 2.5 | 1.25 | E02 | 7.5 | FA-1F-K-E02-162 | 0,51 | Window | 1216Rau0000047209 | 1205Mak0000281450 | 2.2316 | 32 | - | F_Typ5 | Movable | AllplanAttributes (Fenster) - ash D_Detailverweis: <undefiniert>
Fenster | H2 Ebene +2 | 2.5 | 1.25 | E02 | 7.5 | FA-1F-K-E02-161 | 0,51 | Window | 1216Rau0000047209 | 1205Mak0000281586 | 2.2316 | 32 | - | F_Typ5 | Movable | AllplanAttributes (Fenster) - ash D_Detailverweis: <undefiniert>
Fenster | H2 Ebene +2 | 2.5 | 1.25 | E02 | 7.5 | FA-1F-K-E02-159 | 0,51 | Window | 1216Rau0000047223 | 1205Mak0000281446 | 2.2316 | 32 | - | F_Typ5 | Movable | AllplanAttributes (Fenster) - ash D_Detailverweis: <undefiniert>
Fenster | H2 Ebene +2 | 2.5 | 1.25 | E02 | 7.5 | FA-1F-K-E02-154 | 0,51 | Window | 1216Rau0000046499 | 1205Mak0000281331 | 2.2316 | 32 | - | F_Typ5 | Movable | AllplanAttributes (Fenster) - ash D_Detailverweis: <undefiniert>
Fenster | H2 Ebene +1 | 2.5 | 1.25 | E01 | 3.75 | FA-1F-K-E01-095 | 0,51 | Window | 1166Rau0000034085 | 1155Mak0000010242 | 2.2316 | 32 | - | F_Typ5 | Movable
Fenster | H2 Ebene +1 | 2.5 | 1.25 | E01 | 3.75 | FA-1F-K-E01-089 | 0,51 | Window | 1166Rau0000034085 | 1155Mak0813749807 | 2.2316 | 32 | - | F_Typ5 | Movable
Fenster | H2 Ebene +1 | 2.5 | 1.25 | E01 | 3.75 | FA-1F-K-E01-088 | 0,51 | Window | 1166Rau0000034085 | 1155Mak0813749804 | 2.2316 | 32 | - | F_Typ5 | Movable
Fenster | H2 Ebene +1 | 2.5 | 1.25 | E01 | 3.75 | FA-1F-K-E01-091 | 0,51 | Window | 1166Rau0000034085 | 1155Mak0813749810 | 2.2316 | 32 | - | F_Typ5 | Movable
Fenster | H2 Ebene +1 | 2.5 | 1.25 | E01 | 3.75 | FA-1F-K-E01-096 | 0,51 | Window | 1166Rau0000034085 | 1155Mak0000002207 | 2.2316 | 32 | - | F_Typ5 | Movable
Fenster | H2 Ebene +1 | 2.5 | 1.25 | E01 | 3.75 | FA-1F-K-E01-098 | 0,51 | Window | 1166Rau0000034085 | 1155Mak0000002213 | 2.2316 | 32 | - | F_Typ5 | Movable
Fenster | H2 Ebene +1 | 2.5 | 1.25 | E01 | 3.75 | FA-1F-K-E01-099 | 0,51 | Window | 1166Rau0000034085 | 1155Mak0000002216 | 2.2316 | 32 | - | F_Typ5 | Movable
Fenster | H2 Ebene 0 | 2.5 | 1.25 |  |  | FA-1F-K-E00-023 | 0,51 |  | 1116Rau0000065864 | 1105Mak0811566890 | 2.2416 | 32 | RC 2 | F_Typ5 | AllplanAttributes (Fenster) - Positionsnummer_Text: U23
Fenster | H2 Ebene 0 | 2.5 | 1.25 |  |  | FA-1F-K-E00-021 | 0,51 |  | 1116Rau0000065732 | 1105Mak0811566952 | 2.2416 | 32 | RC 2 | F_Typ5 | Movable | AllplanAttributes (Fenster) - Positionsnummer_Text: U23
Fenster | H2 Ebene 0 | 2.5 | 1.25 | E00 | 0 | FA-1F-K-E00-030 | 0,51 | Window | 1116Rau0000065729 | 1105Mak0000047553 | 2.2416 | 32 | RC 2 | F_Typ5 | AllplanAttributes (Fenster) - Positionsnummer_Text: U23; Gewerk: Fensterarbeiten; Pset_WindowCommon - Status: NEW; IsExternal: yes
Fenster | H2 Ebene 0 | 2.5 | 1.25 |  |  | FA-1F-K-E00-027 | 0,51 |  | 1116Rau0000065837 | 1105Mak0000047389 | 2.2416 | 32 | RC 2 | F_Typ5 | AllplanAttributes (Fenster) - Positionsnummer_Text: U23
Fenster | H2 Ebene 0 | 2.5 | 1.25 |  |  | FA-1F-K-E00-029 | 0,51 |  | 1116Rau0000065729 | 1105Mak2005771995 | 2.2416 | 32 | RC 2 | F_Typ5 | AllplanAttributes (Fenster) - Positionsnummer_Text: U23

# IfcWindow: Fenster (11)
Type - PredefinedType: WINDOW; PartitioningType: SINGLE_PANEL; ParameterTakesPrecedence: no
Type - IfcWindowLiningProperties - LiningDepth: 0.07 m; LiningThickness: 0.07 m
AllplanAttributes (Fenster) - V6: 0 m; V7: 0 m; V8: 0 m; V9: 0; Programmversion: 3.0; Bezeichnung: Fenster; Plugin_Bezeichnung: MainObject; Plugin_Objektname: SmartPartCompressed; Glasanteil_berücksichtigen: 100; Version: 6.1; Abrechnungsart: St; Objektname: Fenstermakro, -SmartPart
AllplanQuantities - HeightWindowSillOutside: 0; HeightWindowSillInside: 0; OffsetOpeningBottom: 0; OffsetOpeningTop: 0; OffsetOpeningLeft: 0; OffsetOpeningRight: 0; DeductionOpeningBottom: 70; DeductionOpeningLeft: 70; DeductionOpeningRight: 70; DeductionOpeningTop: 70
Pset_WindowCommon - FireRating: 0; ThermalTransmittance: 0.9 W/K/m2
Name | In | OverallHeight (m) | OverallWidth (m) | Ortscode_Geschoßbezeichnung | OKFF | ash T_Tür-Nr. | g-Wert | Attributset-Objekt | P_ID | Allright_Bauteil_ID | GlassSurface | AcousticRating | SecurityRating | Reference
Fenster | H2 Ebene +3 | 2.5 | 1.25 | E03 | 11.25 | FA_1F-K-E03-201a | 0,35 | Window | 1265Rau0000000005 | 1255Mak0811531418 | 2.2316 | - | - | F_Typ5
Fenster | H2 Ebene +3 | 2.01 | 1.01 | E03 | 11.25 | FA-1F-DK-E03-208 | 0,35 | Window | 1265Rau0000000005 | 1255Mak0811596304 | 1.3629 | - | - | F_Typ45
Fenster | H2 Ebene +3 | 2.01 | 1.01 | E03 | 11.25 | FA-1F-DK-E03-207 | 0,35 | Window | 1265Rau0000000005 | 1255Mak0811596425 | 1.3629 | - | - | F_Typ46
Fenster | H2 Ebene +3 | 1.25 | 1.35 | E03 | 11.25 | FA-1FR-D-E03-L139 | 0,35 | Window | 1266Rau0000012892 | 1255Mak0000004555 | 1.1211 | - | - | F_Typ47
Fenster | H2 Ebene +3 | 1.25 | 1.35 | E03 | 11.25 | FA-1FR-D-E03-L158 | 0,35 | Window | 1266Rau0000012892 | 1255Mak0000002090 | 1.1211 | - | - | F_Typ47
Fenster | H2 Ebene +3 | 2.12 | 0.725 | E03 | 11.25 | FA-1FR-D-E03-L150 | 0,51 | Window | 1266Rau0000015290 | 1255Mak0811537324 | 0.9133 | - | - | F_Typ36 | AllplanAttributes (Fenster) - ash D_Detailverweis: Typ36
Fenster | H2 Ebene +3 | 2.12 | 0.725 | E03 | 11.25 | FA-1FR-D-E03-L152 | 0,51 | Window | 1266Rau0000015290 | 1255Mak0811537377 | 0.9133 | - | - | F_Typ36 | AllplanAttributes (Fenster) - ash D_Detailverweis: Typ36
Fenster | H2 Ebene +2 | 2.5 | 1.25 | E02 | 7.5 | FA-1FR-DK-E02-158 | 0,35 | Window | 1215Rau0000006923 | 1205Mak0000281394 | 2.415 | 32 | - | F_Typ5 | AllplanAttributes (Fenster) - ash D_Detailverweis: <undefiniert>; Sonnenschutztyp: Movable
Fenster | H2 Ebene +2 | 2.5 | 1.25 | E02 | 7.5 | FA-1F-K-E02-152 | 0,51 | Window | 1216Rau0000046485 | 1205Mak0000281326 | 2.2316 | 32 | - | F_Typ5 | AllplanAttributes (Fenster) - ash D_Detailverweis: <undefiniert>; Sonnenschutztyp: Movable
Fenster | H2 Ebene +2 | 2.5 | 1.25 | E02 | 7.5 | FA-1F-K-E02-151 | 0,51 | Window | 1216Rau0000046485 | 1205Mak0000281317 | 2.2316 | 32 | - | F_Typ5 | AllplanAttributes (Fenster) - ash D_Detailverweis: <undefiniert>; Sonnenschutztyp: Movable
Fenster | H2 Ebene 0 | 2.5 | 1.25 |  |  | FA-1F-K-E00-020 | 0,51 |  | 1116Rau0000065732 | 1105Mak0811566921 | 2.2416 | 32 | RC 2 | F_Typ5 | AllplanAttributes (Fenster) - Positionsnummer_Text: U23

# IfcWindow: Fenster
In: H2 Ebene +2
Type - PredefinedType: WINDOW; PartitioningType: TRIPLE_PANEL_BOTTOM; ParameterTakesPrecedence: no
Type - IfcWindowLiningProperties - LiningDepth: 0.07 m; LiningThickness: 0.07 m
OverallHeight: 2.12 m; OverallWidth: 2.6 m
AllplanAttributes (Fenster) - V6: 0 m; V7: 0 m; V8: 0 m; V9: 0; Ortscode_Geschoßbezeichnung: E02; Programmversion: 3.0; Bezeichnung: Fenster; Plugin_Bezeichnung: MainObject; Plugin_Objektname: SmartPartCompressed; Glasanteil_berücksichtigen: 100; Version: 6.1; OKFF: 7.5; ash T_Tür-Nr.: FA-2FLR-D-1S-E02-L110; Sonnenschutztyp: Movable; g-Wert: 0,35; Attributset-Objekt: Window; P_ID: 1216Rau0000046083; Allright_Bauteil_ID: 1205Mak2005859266; Abrechnungsart: St; Objektname: Fenstermakro, -SmartPart
AllplanQuantities - GlassSurface: 4.0546; HeightWindowSillOutside: 0; HeightWindowSillInside: 0; OffsetOpeningBottom: 0; OffsetOpeningTop: 0; OffsetOpeningLeft: 0; OffsetOpeningRight: 0; DeductionOpeningBottom: 70; DeductionOpeningLeft: 70; DeductionOpeningRight: 70; DeductionOpeningTop: 70
Pset_WindowCommon - FireRating: 0; ThermalTransmittance: 0.9 W/K/m2; AcousticRating: 32; SecurityRating: -; Reference: Typ 44

# IfcWindow: Tür (2)
In: H2 Ebene +3
Type - PredefinedType: WINDOW; PartitioningType: DOUBLE_PANEL_VERTICAL; ParameterTakesPrecedence: no
OverallHeight: 2.4 m; OverallWidth: 1.635 m
AllplanAttributes (Tür) - V6: 0 m; V7: 0 m; V8: 0 m; V9: 0; Ortscode_Geschoßbezeichnung: E03; Programmversion: 3.0; Bezeichnung: Tür; Plugin_Bezeichnung: MainObject; Plugin_Objektname: SmartPartCompressed; Glasanteil_berücksichtigen: 100; Version: 6.1; Selbstschließend: yes; g-Wert: 0,35; Attributset-Objekt: Window; Abrechnungsart: St; Objektname: Fenstermakro, -SmartPart
AllplanQuantities - GlassSurface: 2.77134; HeightWindowSillOutside: 0; HeightWindowSillInside: 0; OffsetOpeningBottom: 0; OffsetOpeningTop: 0; OffsetOpeningLeft: 0; OffsetOpeningRight: 0; DeductionOpeningBottom: 20; DeductionOpeningLeft: 70; DeductionOpeningRight: 70; DeductionOpeningTop: 70
Pset_WindowCommon - FireRating: 0; ThermalTransmittance: 1 W/K/m2; AcousticRating: 32; SmokeStop: yes; SecurityRating: RC 1; Reference: T_Typ18
Name | ash T_Tür-Nr. | Allright_Bauteil_ID
Tür | TA-2FRL-D-E03-021 | 1255Mak0000002677
Tür | TA-2FRL-D-E03-020 | 1255Mak0000002680
